VERSION ""

NS_ :

BS_:

BU_: MBMU PC SBMU IMM ETH DCDC LEMS

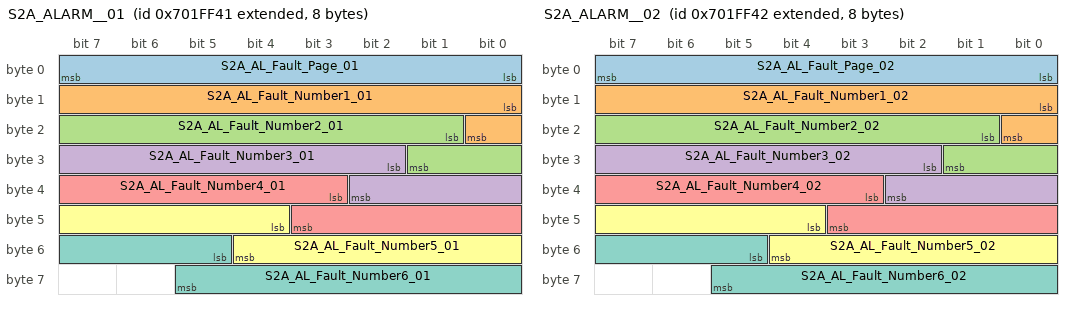
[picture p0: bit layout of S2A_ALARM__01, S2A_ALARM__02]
BO_ 2265055041 S2A_ALARM__01: 8 SBMU
 SG_ S2A_AL_Fault_Page_01 : 0|8@1+ (1,0) [0|255] ""  MBMU,PC
 SG_ S2A_AL_Fault_Number1_01 : 8|9@1+ (1,0) [0|511] ""  MBMU,PC
 SG_ S2A_AL_Fault_Number2_01 : 17|9@1+ (1,0) [0|511] ""  MBMU,PC
 SG_ S2A_AL_Fault_Number3_01 : 26|9@1+ (1,0) [0|511] ""  MBMU,PC
 SG_ S2A_AL_Fault_Number4_01 : 35|9@1+ (1,0) [0|511] ""  MBMU,PC
 SG_ S2A_AL_Fault_Number5_01 : 44|9@1+ (1,0) [0|511] ""  MBMU,PC
 SG_ S2A_AL_Fault_Number6_01 : 53|9@1+ (1,0) [0|511] ""  MBMU,PC

BO_ 2265055042 S2A_ALARM__02: 8 SBMU
 SG_ S2A_AL_Fault_Page_02 : 0|8@1+ (1,0) [0|255] ""  MBMU,PC
 SG_ S2A_AL_Fault_Number1_02 : 8|9@1+ (1,0) [0|511] ""  MBMU,PC
 SG_ S2A_AL_Fault_Number2_02 : 17|9@1+ (1,0) [0|511] ""  MBMU,PC
 SG_ S2A_AL_Fault_Number3_02 : 26|9@1+ (1,0) [0|511] ""  MBMU,PC
 SG_ S2A_AL_Fault_Number4_02 : 35|9@1+ (1,0) [0|511] ""  MBMU,PC
 SG_ S2A_AL_Fault_Number5_02 : 44|9@1+ (1,0) [0|511] ""  MBMU,PC
 SG_ S2A_AL_Fault_Number6_02 : 53|9@1+ (1,0) [0|511] ""  MBMU,PC

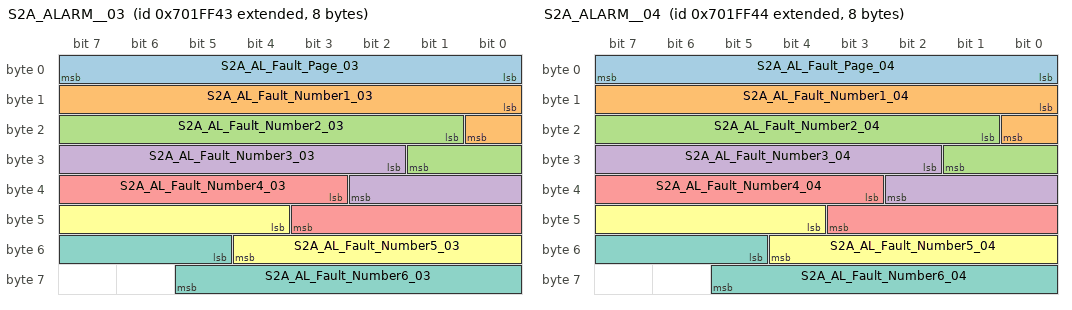
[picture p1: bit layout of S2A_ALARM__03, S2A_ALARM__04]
BO_ 2265055043 S2A_ALARM__03: 8 SBMU
 SG_ S2A_AL_Fault_Page_03 : 0|8@1+ (1,0) [0|255] ""  MBMU,PC
 SG_ S2A_AL_Fault_Number1_03 : 8|9@1+ (1,0) [0|511] ""  MBMU,PC
 SG_ S2A_AL_Fault_Number2_03 : 17|9@1+ (1,0) [0|511] ""  MBMU,PC
 SG_ S2A_AL_Fault_Number3_03 : 26|9@1+ (1,0) [0|511] ""  MBMU,PC
 SG_ S2A_AL_Fault_Number4_03 : 35|9@1+ (1,0) [0|511] ""  MBMU,PC
 SG_ S2A_AL_Fault_Number5_03 : 44|9@1+ (1,0) [0|511] ""  MBMU,PC
 SG_ S2A_AL_Fault_Number6_03 : 53|9@1+ (1,0) [0|511] ""  MBMU,PC

BO_ 2265055044 S2A_ALARM__04: 8 SBMU
 SG_ S2A_AL_Fault_Page_04 : 0|8@1+ (1,0) [0|255] ""  MBMU,PC
 SG_ S2A_AL_Fault_Number1_04 : 8|9@1+ (1,0) [0|511] ""  MBMU,PC
 SG_ S2A_AL_Fault_Number2_04 : 17|9@1+ (1,0) [0|511] ""  MBMU,PC
 SG_ S2A_AL_Fault_Number3_04 : 26|9@1+ (1,0) [0|511] ""  MBMU,PC
 SG_ S2A_AL_Fault_Number4_04 : 35|9@1+ (1,0) [0|511] ""  MBMU,PC
 SG_ S2A_AL_Fault_Number5_04 : 44|9@1+ (1,0) [0|511] ""  MBMU,PC
 SG_ S2A_AL_Fault_Number6_04 : 53|9@1+ (1,0) [0|511] ""  MBMU,PC

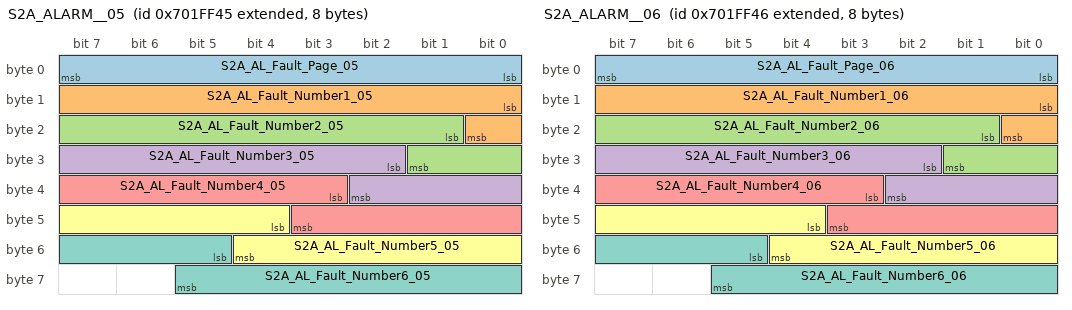
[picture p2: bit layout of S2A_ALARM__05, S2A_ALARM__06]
BO_ 2265055045 S2A_ALARM__05: 8 SBMU
 SG_ S2A_AL_Fault_Page_05 : 0|8@1+ (1,0) [0|255] ""  MBMU,PC
 SG_ S2A_AL_Fault_Number1_05 : 8|9@1+ (1,0) [0|511] ""  MBMU,PC
 SG_ S2A_AL_Fault_Number2_05 : 17|9@1+ (1,0) [0|511] ""  MBMU,PC
 SG_ S2A_AL_Fault_Number3_05 : 26|9@1+ (1,0) [0|511] ""  MBMU,PC
 SG_ S2A_AL_Fault_Number4_05 : 35|9@1+ (1,0) [0|511] ""  MBMU,PC
 SG_ S2A_AL_Fault_Number5_05 : 44|9@1+ (1,0) [0|511] ""  MBMU,PC
 SG_ S2A_AL_Fault_Number6_05 : 53|9@1+ (1,0) [0|511] ""  MBMU,PC

BO_ 2265055046 S2A_ALARM__06: 8 SBMU
 SG_ S2A_AL_Fault_Page_06 : 0|8@1+ (1,0) [0|255] ""  MBMU,PC
 SG_ S2A_AL_Fault_Number1_06 : 8|9@1+ (1,0) [0|511] ""  MBMU,PC
 SG_ S2A_AL_Fault_Number2_06 : 17|9@1+ (1,0) [0|511] ""  MBMU,PC
 SG_ S2A_AL_Fault_Number3_06 : 26|9@1+ (1,0) [0|511] ""  MBMU,PC
 SG_ S2A_AL_Fault_Number4_06 : 35|9@1+ (1,0) [0|511] ""  MBMU,PC
 SG_ S2A_AL_Fault_Number5_06 : 44|9@1+ (1,0) [0|511] ""  MBMU,PC
 SG_ S2A_AL_Fault_Number6_06 : 53|9@1+ (1,0) [0|511] ""  MBMU,PC

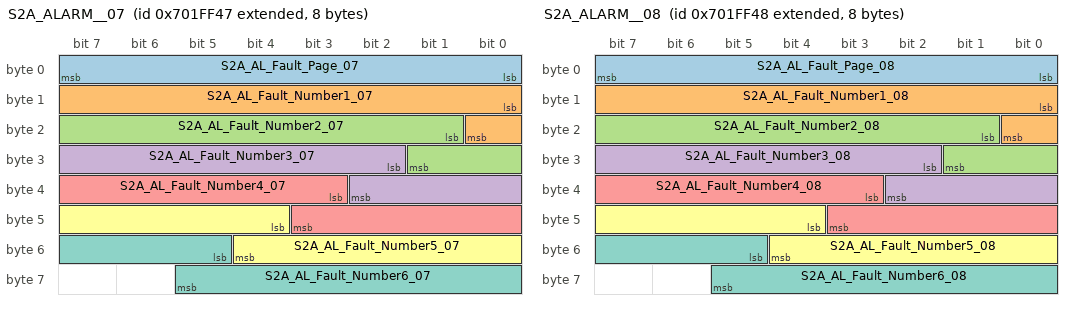
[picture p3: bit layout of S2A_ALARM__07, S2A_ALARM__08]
BO_ 2265055047 S2A_ALARM__07: 8 SBMU
 SG_ S2A_AL_Fault_Page_07 : 0|8@1+ (1,0) [0|255] ""  MBMU,PC
 SG_ S2A_AL_Fault_Number1_07 : 8|9@1+ (1,0) [0|511] ""  MBMU,PC
 SG_ S2A_AL_Fault_Number2_07 : 17|9@1+ (1,0) [0|511] ""  MBMU,PC
 SG_ S2A_AL_Fault_Number3_07 : 26|9@1+ (1,0) [0|511] ""  MBMU,PC
 SG_ S2A_AL_Fault_Number4_07 : 35|9@1+ (1,0) [0|511] ""  MBMU,PC
 SG_ S2A_AL_Fault_Number5_07 : 44|9@1+ (1,0) [0|511] ""  MBMU,PC
 SG_ S2A_AL_Fault_Number6_07 : 53|9@1+ (1,0) [0|511] ""  MBMU,PC

BO_ 2265055048 S2A_ALARM__08: 8 SBMU
 SG_ S2A_AL_Fault_Page_08 : 0|8@1+ (1,0) [0|255] ""  MBMU,PC
 SG_ S2A_AL_Fault_Number1_08 : 8|9@1+ (1,0) [0|511] ""  MBMU,PC
 SG_ S2A_AL_Fault_Number2_08 : 17|9@1+ (1,0) [0|511] ""  MBMU,PC
 SG_ S2A_AL_Fault_Number3_08 : 26|9@1+ (1,0) [0|511] ""  MBMU,PC
 SG_ S2A_AL_Fault_Number4_08 : 35|9@1+ (1,0) [0|511] ""  MBMU,PC
 SG_ S2A_AL_Fault_Number5_08 : 44|9@1+ (1,0) [0|511] ""  MBMU,PC
 SG_ S2A_AL_Fault_Number6_08 : 53|9@1+ (1,0) [0|511] ""  MBMU,PC

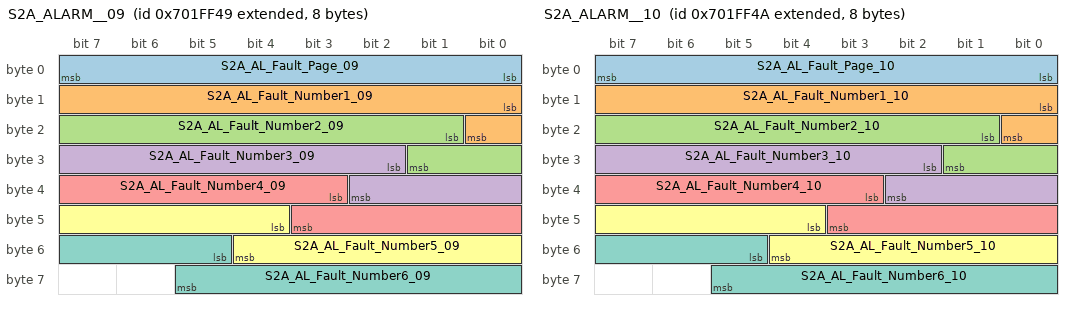
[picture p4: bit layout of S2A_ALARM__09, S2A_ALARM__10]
BO_ 2265055049 S2A_ALARM__09: 8 SBMU
 SG_ S2A_AL_Fault_Page_09 : 0|8@1+ (1,0) [0|255] ""  MBMU,PC
 SG_ S2A_AL_Fault_Number1_09 : 8|9@1+ (1,0) [0|511] ""  MBMU,PC
 SG_ S2A_AL_Fault_Number2_09 : 17|9@1+ (1,0) [0|511] ""  MBMU,PC
 SG_ S2A_AL_Fault_Number3_09 : 26|9@1+ (1,0) [0|511] ""  MBMU,PC
 SG_ S2A_AL_Fault_Number4_09 : 35|9@1+ (1,0) [0|511] ""  MBMU,PC
 SG_ S2A_AL_Fault_Number5_09 : 44|9@1+ (1,0) [0|511] ""  MBMU,PC
 SG_ S2A_AL_Fault_Number6_09 : 53|9@1+ (1,0) [0|511] ""  MBMU,PC

BO_ 2265055050 S2A_ALARM__10: 8 SBMU
 SG_ S2A_AL_Fault_Page_10 : 0|8@1+ (1,0) [0|255] ""  MBMU,PC
 SG_ S2A_AL_Fault_Number1_10 : 8|9@1+ (1,0) [0|511] ""  MBMU,PC
 SG_ S2A_AL_Fault_Number2_10 : 17|9@1+ (1,0) [0|511] ""  MBMU,PC
 SG_ S2A_AL_Fault_Number3_10 : 26|9@1+ (1,0) [0|511] ""  MBMU,PC
 SG_ S2A_AL_Fault_Number4_10 : 35|9@1+ (1,0) [0|511] ""  MBMU,PC
 SG_ S2A_AL_Fault_Number5_10 : 44|9@1+ (1,0) [0|511] ""  MBMU,PC
 SG_ S2A_AL_Fault_Number6_10 : 53|9@1+ (1,0) [0|511] ""  MBMU,PC

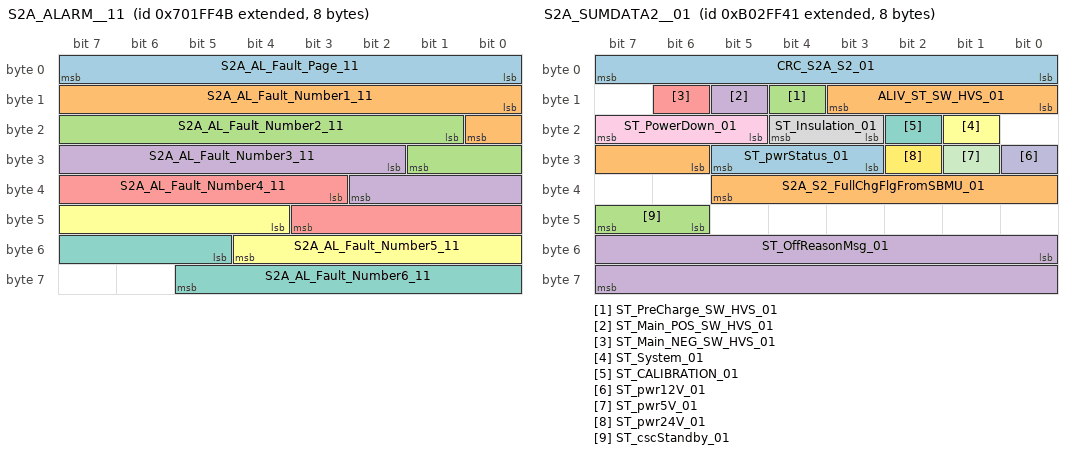
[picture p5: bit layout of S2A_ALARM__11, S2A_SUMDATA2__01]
BO_ 2265055051 S2A_ALARM__11: 8 SBMU
 SG_ S2A_AL_Fault_Page_11 : 0|8@1+ (1,0) [0|255] ""  MBMU,PC
 SG_ S2A_AL_Fault_Number1_11 : 8|9@1+ (1,0) [0|511] ""  MBMU,PC
 SG_ S2A_AL_Fault_Number2_11 : 17|9@1+ (1,0) [0|511] ""  MBMU,PC
 SG_ S2A_AL_Fault_Number3_11 : 26|9@1+ (1,0) [0|511] ""  MBMU,PC
 SG_ S2A_AL_Fault_Number4_11 : 35|9@1+ (1,0) [0|511] ""  MBMU,PC
 SG_ S2A_AL_Fault_Number5_11 : 44|9@1+ (1,0) [0|511] ""  MBMU,PC
 SG_ S2A_AL_Fault_Number6_11 : 53|9@1+ (1,0) [0|511] ""  MBMU,PC

BO_ 2265055052 S2A_ALARM__12: 8 SBMU
 SG_ S2A_AL_Fault_Page_12 : 0|8@1+ (1,0) [0|255] ""  MBMU,PC
 SG_ S2A_AL_Fault_Number1_12 : 8|9@1+ (1,0) [0|511] ""  MBMU,PC
 SG_ S2A_AL_Fault_Number2_12 : 17|9@1+ (1,0) [0|511] ""  MBMU,PC
 SG_ S2A_AL_Fault_Number3_12 : 26|9@1+ (1,0) [0|511] ""  MBMU,PC
 SG_ S2A_AL_Fault_Number4_12 : 35|9@1+ (1,0) [0|511] ""  MBMU,PC
 SG_ S2A_AL_Fault_Number5_12 : 44|9@1+ (1,0) [0|511] ""  MBMU,PC
 SG_ S2A_AL_Fault_Number6_12 : 53|9@1+ (1,0) [0|511] ""  MBMU,PC

BO_ 2265055053 S2A_ALARM__13: 8 SBMU
 SG_ S2A_AL_Fault_Page_13 : 0|8@1+ (1,0) [0|255] ""  MBMU,PC
 SG_ S2A_AL_Fault_Number1_13 : 8|9@1+ (1,0) [0|511] ""  MBMU,PC
 SG_ S2A_AL_Fault_Number2_13 : 17|9@1+ (1,0) [0|511] ""  MBMU,PC
 SG_ S2A_AL_Fault_Number3_13 : 26|9@1+ (1,0) [0|511] ""  MBMU,PC
 SG_ S2A_AL_Fault_Number4_13 : 35|9@1+ (1,0) [0|511] ""  MBMU,PC
 SG_ S2A_AL_Fault_Number5_13 : 44|9@1+ (1,0) [0|511] ""  MBMU,PC
 SG_ S2A_AL_Fault_Number6_13 : 53|9@1+ (1,0) [0|511] ""  MBMU,PC

BO_ 2265055054 S2A_ALARM__14: 8 SBMU
 SG_ S2A_AL_Fault_Page_14 : 0|8@1+ (1,0) [0|255] ""  MBMU,PC
 SG_ S2A_AL_Fault_Number1_14 : 8|9@1+ (1,0) [0|511] ""  MBMU,PC
 SG_ S2A_AL_Fault_Number2_14 : 17|9@1+ (1,0) [0|511] ""  MBMU,PC
 SG_ S2A_AL_Fault_Number3_14 : 26|9@1+ (1,0) [0|511] ""  MBMU,PC
 SG_ S2A_AL_Fault_Number4_14 : 35|9@1+ (1,0) [0|511] ""  MBMU,PC
 SG_ S2A_AL_Fault_Number5_14 : 44|9@1+ (1,0) [0|511] ""  MBMU,PC
 SG_ S2A_AL_Fault_Number6_14 : 53|9@1+ (1,0) [0|511] ""  MBMU,PC

BO_ 2265055055 S2A_ALARM__15: 8 SBMU
 SG_ S2A_AL_Fault_Page_15 : 0|8@1+ (1,0) [0|255] ""  MBMU,PC
 SG_ S2A_AL_Fault_Number1_15 : 8|9@1+ (1,0) [0|511] ""  MBMU,PC
 SG_ S2A_AL_Fault_Number2_15 : 17|9@1+ (1,0) [0|511] ""  MBMU,PC
 SG_ S2A_AL_Fault_Number3_15 : 26|9@1+ (1,0) [0|511] ""  MBMU,PC
 SG_ S2A_AL_Fault_Number4_15 : 35|9@1+ (1,0) [0|511] ""  MBMU,PC
 SG_ S2A_AL_Fault_Number5_15 : 44|9@1+ (1,0) [0|511] ""  MBMU,PC
 SG_ S2A_AL_Fault_Number6_15 : 53|9@1+ (1,0) [0|511] ""  MBMU,PC

BO_ 2265055056 S2A_ALARM__16: 8 SBMU
 SG_ S2A_AL_Fault_Page_16 : 0|8@1+ (1,0) [0|255] ""  MBMU,PC
 SG_ S2A_AL_Fault_Number1_16 : 8|9@1+ (1,0) [0|511] ""  MBMU,PC
 SG_ S2A_AL_Fault_Number2_16 : 17|9@1+ (1,0) [0|511] ""  MBMU,PC
 SG_ S2A_AL_Fault_Number3_16 : 26|9@1+ (1,0) [0|511] ""  MBMU,PC
 SG_ S2A_AL_Fault_Number4_16 : 35|9@1+ (1,0) [0|511] ""  MBMU,PC
 SG_ S2A_AL_Fault_Number5_16 : 44|9@1+ (1,0) [0|511] ""  MBMU,PC
 SG_ S2A_AL_Fault_Number6_16 : 53|9@1+ (1,0) [0|511] ""  MBMU,PC

BO_ 2265055057 S2A_ALARM__17: 8 SBMU
 SG_ S2A_AL_Fault_Page_17 : 0|8@1+ (1,0) [0|255] ""  MBMU,PC
 SG_ S2A_AL_Fault_Number1_17 : 8|9@1+ (1,0) [0|511] ""  MBMU,PC
 SG_ S2A_AL_Fault_Number2_17 : 17|9@1+ (1,0) [0|511] ""  MBMU,PC
 SG_ S2A_AL_Fault_Number3_17 : 26|9@1+ (1,0) [0|511] ""  MBMU,PC
 SG_ S2A_AL_Fault_Number4_17 : 35|9@1+ (1,0) [0|511] ""  MBMU,PC
 SG_ S2A_AL_Fault_Number5_17 : 44|9@1+ (1,0) [0|511] ""  MBMU,PC
 SG_ S2A_AL_Fault_Number6_17 : 53|9@1+ (1,0) [0|511] ""  MBMU,PC

BO_ 2265055058 S2A_ALARM__18: 8 SBMU
 SG_ S2A_AL_Fault_Page_18 : 0|8@1+ (1,0) [0|255] ""  MBMU,PC
 SG_ S2A_AL_Fault_Number1_18 : 8|9@1+ (1,0) [0|511] ""  MBMU,PC
 SG_ S2A_AL_Fault_Number2_18 : 17|9@1+ (1,0) [0|511] ""  MBMU,PC
 SG_ S2A_AL_Fault_Number3_18 : 26|9@1+ (1,0) [0|511] ""  MBMU,PC
 SG_ S2A_AL_Fault_Number4_18 : 35|9@1+ (1,0) [0|511] ""  MBMU,PC
 SG_ S2A_AL_Fault_Number5_18 : 44|9@1+ (1,0) [0|511] ""  MBMU,PC
 SG_ S2A_AL_Fault_Number6_18 : 53|9@1+ (1,0) [0|511] ""  MBMU,PC

BO_ 2265055059 S2A_ALARM__19: 8 SBMU
 SG_ S2A_AL_Fault_Page_19 : 0|8@1+ (1,0) [0|255] ""  MBMU,PC
 SG_ S2A_AL_Fault_Number1_19 : 8|9@1+ (1,0) [0|511] ""  MBMU,PC
 SG_ S2A_AL_Fault_Number2_19 : 17|9@1+ (1,0) [0|511] ""  MBMU,PC
 SG_ S2A_AL_Fault_Number3_19 : 26|9@1+ (1,0) [0|511] ""  MBMU,PC
 SG_ S2A_AL_Fault_Number4_19 : 35|9@1+ (1,0) [0|511] ""  MBMU,PC
 SG_ S2A_AL_Fault_Number5_19 : 44|9@1+ (1,0) [0|511] ""  MBMU,PC
 SG_ S2A_AL_Fault_Number6_19 : 53|9@1+ (1,0) [0|511] ""  MBMU,PC

BO_ 2265055060 S2A_ALARM__20: 8 SBMU
 SG_ S2A_AL_Fault_Page_20 : 0|8@1+ (1,0) [0|255] ""  MBMU,PC
 SG_ S2A_AL_Fault_Number1_20 : 8|9@1+ (1,0) [0|511] ""  MBMU,PC
 SG_ S2A_AL_Fault_Number2_20 : 17|9@1+ (1,0) [0|511] ""  MBMU,PC
 SG_ S2A_AL_Fault_Number3_20 : 26|9@1+ (1,0) [0|511] ""  MBMU,PC
 SG_ S2A_AL_Fault_Number4_20 : 35|9@1+ (1,0) [0|511] ""  MBMU,PC
 SG_ S2A_AL_Fault_Number5_20 : 44|9@1+ (1,0) [0|511] ""  MBMU,PC
 SG_ S2A_AL_Fault_Number6_20 : 53|9@1+ (1,0) [0|511] ""  MBMU,PC

BO_ 2265055061 S2A_ALARM__21: 8 SBMU
 SG_ S2A_AL_Fault_Page_21 : 0|8@1+ (1,0) [0|255] ""  MBMU,PC
 SG_ S2A_AL_Fault_Number1_21 : 8|9@1+ (1,0) [0|511] ""  MBMU,PC
 SG_ S2A_AL_Fault_Number2_21 : 17|9@1+ (1,0) [0|511] ""  MBMU,PC
 SG_ S2A_AL_Fault_Number3_21 : 26|9@1+ (1,0) [0|511] ""  MBMU,PC
 SG_ S2A_AL_Fault_Number4_21 : 35|9@1+ (1,0) [0|511] ""  MBMU,PC
 SG_ S2A_AL_Fault_Number5_21 : 44|9@1+ (1,0) [0|511] ""  MBMU,PC
 SG_ S2A_AL_Fault_Number6_21 : 53|9@1+ (1,0) [0|511] ""  MBMU,PC

BO_ 2265055062 S2A_ALARM__22: 8 SBMU
 SG_ S2A_AL_Fault_Page_22 : 0|8@1+ (1,0) [0|255] ""  MBMU,PC
 SG_ S2A_AL_Fault_Number1_22 : 8|9@1+ (1,0) [0|511] ""  MBMU,PC
 SG_ S2A_AL_Fault_Number2_22 : 17|9@1+ (1,0) [0|511] ""  MBMU,PC
 SG_ S2A_AL_Fault_Number3_22 : 26|9@1+ (1,0) [0|511] ""  MBMU,PC
 SG_ S2A_AL_Fault_Number4_22 : 35|9@1+ (1,0) [0|511] ""  MBMU,PC
 SG_ S2A_AL_Fault_Number5_22 : 44|9@1+ (1,0) [0|511] ""  MBMU,PC
 SG_ S2A_AL_Fault_Number6_22 : 53|9@1+ (1,0) [0|511] ""  MBMU,PC

BO_ 2265055063 S2A_ALARM__23: 8 SBMU
 SG_ S2A_AL_Fault_Page_23 : 0|8@1+ (1,0) [0|255] ""  MBMU,PC
 SG_ S2A_AL_Fault_Number1_23 : 8|9@1+ (1,0) [0|511] ""  MBMU,PC
 SG_ S2A_AL_Fault_Number2_23 : 17|9@1+ (1,0) [0|511] ""  MBMU,PC
 SG_ S2A_AL_Fault_Number3_23 : 26|9@1+ (1,0) [0|511] ""  MBMU,PC
 SG_ S2A_AL_Fault_Number4_23 : 35|9@1+ (1,0) [0|511] ""  MBMU,PC
 SG_ S2A_AL_Fault_Number5_23 : 44|9@1+ (1,0) [0|511] ""  MBMU,PC
 SG_ S2A_AL_Fault_Number6_23 : 53|9@1+ (1,0) [0|511] ""  MBMU,PC

BO_ 2265055064 S2A_ALARM__24: 8 SBMU
 SG_ S2A_AL_Fault_Page_24 : 0|8@1+ (1,0) [0|255] ""  MBMU,PC
 SG_ S2A_AL_Fault_Number1_24 : 8|9@1+ (1,0) [0|511] ""  MBMU,PC
 SG_ S2A_AL_Fault_Number2_24 : 17|9@1+ (1,0) [0|511] ""  MBMU,PC
 SG_ S2A_AL_Fault_Number3_24 : 26|9@1+ (1,0) [0|511] ""  MBMU,PC
 SG_ S2A_AL_Fault_Number4_24 : 35|9@1+ (1,0) [0|511] ""  MBMU,PC
 SG_ S2A_AL_Fault_Number5_24 : 44|9@1+ (1,0) [0|511] ""  MBMU,PC
 SG_ S2A_AL_Fault_Number6_24 : 53|9@1+ (1,0) [0|511] ""  MBMU,PC

BO_ 2265055065 S2A_ALARM__25: 8 SBMU
 SG_ S2A_AL_Fault_Page_25 : 0|8@1+ (1,0) [0|255] ""  MBMU,PC
 SG_ S2A_AL_Fault_Number1_25 : 8|9@1+ (1,0) [0|511] ""  MBMU,PC
 SG_ S2A_AL_Fault_Number2_25 : 17|9@1+ (1,0) [0|511] ""  MBMU,PC
 SG_ S2A_AL_Fault_Number3_25 : 26|9@1+ (1,0) [0|511] ""  MBMU,PC
 SG_ S2A_AL_Fault_Number4_25 : 35|9@1+ (1,0) [0|511] ""  MBMU,PC
 SG_ S2A_AL_Fault_Number5_25 : 44|9@1+ (1,0) [0|511] ""  MBMU,PC
 SG_ S2A_AL_Fault_Number6_25 : 53|9@1+ (1,0) [0|511] ""  MBMU,PC

BO_ 2265055066 S2A_ALARM__26: 8 SBMU
 SG_ S2A_AL_Fault_Page_26 : 0|8@1+ (1,0) [0|255] ""  MBMU,PC
 SG_ S2A_AL_Fault_Number1_26 : 8|9@1+ (1,0) [0|511] ""  MBMU,PC
 SG_ S2A_AL_Fault_Number2_26 : 17|9@1+ (1,0) [0|511] ""  MBMU,PC
 SG_ S2A_AL_Fault_Number3_26 : 26|9@1+ (1,0) [0|511] ""  MBMU,PC
 SG_ S2A_AL_Fault_Number4_26 : 35|9@1+ (1,0) [0|511] ""  MBMU,PC
 SG_ S2A_AL_Fault_Number5_26 : 44|9@1+ (1,0) [0|511] ""  MBMU,PC
 SG_ S2A_AL_Fault_Number6_26 : 53|9@1+ (1,0) [0|511] ""  MBMU,PC

BO_ 2265055067 S2A_ALARM__27: 8 SBMU
 SG_ S2A_AL_Fault_Page_27 : 0|8@1+ (1,0) [0|255] ""  MBMU,PC
 SG_ S2A_AL_Fault_Number1_27 : 8|9@1+ (1,0) [0|511] ""  MBMU,PC
 SG_ S2A_AL_Fault_Number2_27 : 17|9@1+ (1,0) [0|511] ""  MBMU,PC
 SG_ S2A_AL_Fault_Number3_27 : 26|9@1+ (1,0) [0|511] ""  MBMU,PC
 SG_ S2A_AL_Fault_Number4_27 : 35|9@1+ (1,0) [0|511] ""  MBMU,PC
 SG_ S2A_AL_Fault_Number5_27 : 44|9@1+ (1,0) [0|511] ""  MBMU,PC
 SG_ S2A_AL_Fault_Number6_27 : 53|9@1+ (1,0) [0|511] ""  MBMU,PC

BO_ 2265055068 S2A_ALARM__28: 8 SBMU
 SG_ S2A_AL_Fault_Page_28 : 0|8@1+ (1,0) [0|255] ""  MBMU,PC
 SG_ S2A_AL_Fault_Number1_28 : 8|9@1+ (1,0) [0|511] ""  MBMU,PC
 SG_ S2A_AL_Fault_Number2_28 : 17|9@1+ (1,0) [0|511] ""  MBMU,PC
 SG_ S2A_AL_Fault_Number3_28 : 26|9@1+ (1,0) [0|511] ""  MBMU,PC
 SG_ S2A_AL_Fault_Number4_28 : 35|9@1+ (1,0) [0|511] ""  MBMU,PC
 SG_ S2A_AL_Fault_Number5_28 : 44|9@1+ (1,0) [0|511] ""  MBMU,PC
 SG_ S2A_AL_Fault_Number6_28 : 53|9@1+ (1,0) [0|511] ""  MBMU,PC

BO_ 2265055069 S2A_ALARM__29: 8 SBMU
 SG_ S2A_AL_Fault_Page_29 : 0|8@1+ (1,0) [0|255] ""  MBMU,PC
 SG_ S2A_AL_Fault_Number1_29 : 8|9@1+ (1,0) [0|511] ""  MBMU,PC
 SG_ S2A_AL_Fault_Number2_29 : 17|9@1+ (1,0) [0|511] ""  MBMU,PC
 SG_ S2A_AL_Fault_Number3_29 : 26|9@1+ (1,0) [0|511] ""  MBMU,PC
 SG_ S2A_AL_Fault_Number4_29 : 35|9@1+ (1,0) [0|511] ""  MBMU,PC
 SG_ S2A_AL_Fault_Number5_29 : 44|9@1+ (1,0) [0|511] ""  MBMU,PC
 SG_ S2A_AL_Fault_Number6_29 : 53|9@1+ (1,0) [0|511] ""  MBMU,PC

BO_ 2265055070 S2A_ALARM__30: 8 SBMU
 SG_ S2A_AL_Fault_Page_30 : 0|8@1+ (1,0) [0|255] ""  MBMU,PC
 SG_ S2A_AL_Fault_Number1_30 : 8|9@1+ (1,0) [0|511] ""  MBMU,PC
 SG_ S2A_AL_Fault_Number2_30 : 17|9@1+ (1,0) [0|511] ""  MBMU,PC
 SG_ S2A_AL_Fault_Number3_30 : 26|9@1+ (1,0) [0|511] ""  MBMU,PC
 SG_ S2A_AL_Fault_Number4_30 : 35|9@1+ (1,0) [0|511] ""  MBMU,PC
 SG_ S2A_AL_Fault_Number5_30 : 44|9@1+ (1,0) [0|511] ""  MBMU,PC
 SG_ S2A_AL_Fault_Number6_30 : 53|9@1+ (1,0) [0|511] ""  MBMU,PC

BO_ 2265055071 S2A_ALARM__31: 8 SBMU
 SG_ S2A_AL_Fault_Page_31 : 0|8@1+ (1,0) [0|255] ""  MBMU,PC
 SG_ S2A_AL_Fault_Number1_31 : 8|9@1+ (1,0) [0|511] ""  MBMU,PC
 SG_ S2A_AL_Fault_Number2_31 : 17|9@1+ (1,0) [0|511] ""  MBMU,PC
 SG_ S2A_AL_Fault_Number3_31 : 26|9@1+ (1,0) [0|511] ""  MBMU,PC
 SG_ S2A_AL_Fault_Number4_31 : 35|9@1+ (1,0) [0|511] ""  MBMU,PC
 SG_ S2A_AL_Fault_Number5_31 : 44|9@1+ (1,0) [0|511] ""  MBMU,PC
 SG_ S2A_AL_Fault_Number6_31 : 53|9@1+ (1,0) [0|511] ""  MBMU,PC

BO_ 2265055072 S2A_ALARM__32: 8 SBMU
 SG_ S2A_AL_Fault_Page_32 : 0|8@1+ (1,0) [0|255] ""  MBMU,PC
 SG_ S2A_AL_Fault_Number1_32 : 8|9@1+ (1,0) [0|511] ""  MBMU,PC
 SG_ S2A_AL_Fault_Number2_32 : 17|9@1+ (1,0) [0|511] ""  MBMU,PC
 SG_ S2A_AL_Fault_Number3_32 : 26|9@1+ (1,0) [0|511] ""  MBMU,PC
 SG_ S2A_AL_Fault_Number4_32 : 35|9@1+ (1,0) [0|511] ""  MBMU,PC
 SG_ S2A_AL_Fault_Number5_32 : 44|9@1+ (1,0) [0|511] ""  MBMU,PC
 SG_ S2A_AL_Fault_Number6_32 : 53|9@1+ (1,0) [0|511] ""  MBMU,PC

BO_ 2265055073 S2A_ALARM__33: 8 SBMU
 SG_ S2A_AL_Fault_Page_33 : 0|8@1+ (1,0) [0|255] ""  MBMU,PC
 SG_ S2A_AL_Fault_Number1_33 : 8|9@1+ (1,0) [0|511] ""  MBMU,PC
 SG_ S2A_AL_Fault_Number2_33 : 17|9@1+ (1,0) [0|511] ""  MBMU,PC
 SG_ S2A_AL_Fault_Number3_33 : 26|9@1+ (1,0) [0|511] ""  MBMU,PC
 SG_ S2A_AL_Fault_Number4_33 : 35|9@1+ (1,0) [0|511] ""  MBMU,PC
 SG_ S2A_AL_Fault_Number5_33 : 44|9@1+ (1,0) [0|511] ""  MBMU,PC
 SG_ S2A_AL_Fault_Number6_33 : 53|9@1+ (1,0) [0|511] ""  MBMU,PC

BO_ 2265055074 S2A_ALARM__34: 8 SBMU
 SG_ S2A_AL_Fault_Page_34 : 0|8@1+ (1,0) [0|255] ""  MBMU,PC
 SG_ S2A_AL_Fault_Number1_34 : 8|9@1+ (1,0) [0|511] ""  MBMU,PC
 SG_ S2A_AL_Fault_Number2_34 : 17|9@1+ (1,0) [0|511] ""  MBMU,PC
 SG_ S2A_AL_Fault_Number3_34 : 26|9@1+ (1,0) [0|511] ""  MBMU,PC
 SG_ S2A_AL_Fault_Number4_34 : 35|9@1+ (1,0) [0|511] ""  MBMU,PC
 SG_ S2A_AL_Fault_Number5_34 : 44|9@1+ (1,0) [0|511] ""  MBMU,PC
 SG_ S2A_AL_Fault_Number6_34 : 53|9@1+ (1,0) [0|511] ""  MBMU,PC

BO_ 2265055075 S2A_ALARM__35: 8 SBMU
 SG_ S2A_AL_Fault_Page_35 : 0|8@1+ (1,0) [0|255] ""  MBMU,PC
 SG_ S2A_AL_Fault_Number1_35 : 8|9@1+ (1,0) [0|511] ""  MBMU,PC
 SG_ S2A_AL_Fault_Number2_35 : 17|9@1+ (1,0) [0|511] ""  MBMU,PC
 SG_ S2A_AL_Fault_Number3_35 : 26|9@1+ (1,0) [0|511] ""  MBMU,PC
 SG_ S2A_AL_Fault_Number4_35 : 35|9@1+ (1,0) [0|511] ""  MBMU,PC
 SG_ S2A_AL_Fault_Number5_35 : 44|9@1+ (1,0) [0|511] ""  MBMU,PC
 SG_ S2A_AL_Fault_Number6_35 : 53|9@1+ (1,0) [0|511] ""  MBMU,PC

BO_ 2265055076 S2A_ALARM__36: 8 SBMU
 SG_ S2A_AL_Fault_Page_36 : 0|8@1+ (1,0) [0|255] ""  MBMU,PC
 SG_ S2A_AL_Fault_Number1_36 : 8|9@1+ (1,0) [0|511] ""  MBMU,PC
 SG_ S2A_AL_Fault_Number2_36 : 17|9@1+ (1,0) [0|511] ""  MBMU,PC
 SG_ S2A_AL_Fault_Number3_36 : 26|9@1+ (1,0) [0|511] ""  MBMU,PC
 SG_ S2A_AL_Fault_Number4_36 : 35|9@1+ (1,0) [0|511] ""  MBMU,PC
 SG_ S2A_AL_Fault_Number5_36 : 44|9@1+ (1,0) [0|511] ""  MBMU,PC
 SG_ S2A_AL_Fault_Number6_36 : 53|9@1+ (1,0) [0|511] ""  MBMU,PC

BO_ 2265055077 S2A_ALARM__37: 8 SBMU
 SG_ S2A_AL_Fault_Page_37 : 0|8@1+ (1,0) [0|255] ""  MBMU,PC
 SG_ S2A_AL_Fault_Number1_37 : 8|9@1+ (1,0) [0|511] ""  MBMU,PC
 SG_ S2A_AL_Fault_Number2_37 : 17|9@1+ (1,0) [0|511] ""  MBMU,PC
 SG_ S2A_AL_Fault_Number3_37 : 26|9@1+ (1,0) [0|511] ""  MBMU,PC
 SG_ S2A_AL_Fault_Number4_37 : 35|9@1+ (1,0) [0|511] ""  MBMU,PC
 SG_ S2A_AL_Fault_Number5_37 : 44|9@1+ (1,0) [0|511] ""  MBMU,PC
 SG_ S2A_AL_Fault_Number6_37 : 53|9@1+ (1,0) [0|511] ""  MBMU,PC

BO_ 2265055078 S2A_ALARM__38: 8 SBMU
 SG_ S2A_AL_Fault_Page_38 : 0|8@1+ (1,0) [0|255] ""  MBMU,PC
 SG_ S2A_AL_Fault_Number1_38 : 8|9@1+ (1,0) [0|511] ""  MBMU,PC
 SG_ S2A_AL_Fault_Number2_38 : 17|9@1+ (1,0) [0|511] ""  MBMU,PC
 SG_ S2A_AL_Fault_Number3_38 : 26|9@1+ (1,0) [0|511] ""  MBMU,PC
 SG_ S2A_AL_Fault_Number4_38 : 35|9@1+ (1,0) [0|511] ""  MBMU,PC
 SG_ S2A_AL_Fault_Number5_38 : 44|9@1+ (1,0) [0|511] ""  MBMU,PC
 SG_ S2A_AL_Fault_Number6_38 : 53|9@1+ (1,0) [0|511] ""  MBMU,PC

BO_ 2265055079 S2A_ALARM__39: 8 SBMU
 SG_ S2A_AL_Fault_Page_39 : 0|8@1+ (1,0) [0|255] ""  MBMU,PC
 SG_ S2A_AL_Fault_Number1_39 : 8|9@1+ (1,0) [0|511] ""  MBMU,PC
 SG_ S2A_AL_Fault_Number2_39 : 17|9@1+ (1,0) [0|511] ""  MBMU,PC
 SG_ S2A_AL_Fault_Number3_39 : 26|9@1+ (1,0) [0|511] ""  MBMU,PC
 SG_ S2A_AL_Fault_Number4_39 : 35|9@1+ (1,0) [0|511] ""  MBMU,PC
 SG_ S2A_AL_Fault_Number5_39 : 44|9@1+ (1,0) [0|511] ""  MBMU,PC
 SG_ S2A_AL_Fault_Number6_39 : 53|9@1+ (1,0) [0|511] ""  MBMU,PC

BO_ 2265055080 S2A_ALARM__40: 8 SBMU
 SG_ S2A_AL_Fault_Page_40 : 0|8@1+ (1,0) [0|255] ""  MBMU,PC
 SG_ S2A_AL_Fault_Number1_40 : 8|9@1+ (1,0) [0|511] ""  MBMU,PC
 SG_ S2A_AL_Fault_Number2_40 : 17|9@1+ (1,0) [0|511] ""  MBMU,PC
 SG_ S2A_AL_Fault_Number3_40 : 26|9@1+ (1,0) [0|511] ""  MBMU,PC
 SG_ S2A_AL_Fault_Number4_40 : 35|9@1+ (1,0) [0|511] ""  MBMU,PC
 SG_ S2A_AL_Fault_Number5_40 : 44|9@1+ (1,0) [0|511] ""  MBMU,PC
 SG_ S2A_AL_Fault_Number6_40 : 53|9@1+ (1,0) [0|511] ""  MBMU,PC

BO_ 2265055081 S2A_ALARM__41: 8 SBMU
 SG_ S2A_AL_Fault_Page_41 : 0|8@1+ (1,0) [0|255] ""  MBMU,PC
 SG_ S2A_AL_Fault_Number1_41 : 8|9@1+ (1,0) [0|511] ""  MBMU,PC
 SG_ S2A_AL_Fault_Number2_41 : 17|9@1+ (1,0) [0|511] ""  MBMU,PC
 SG_ S2A_AL_Fault_Number3_41 : 26|9@1+ (1,0) [0|511] ""  MBMU,PC
 SG_ S2A_AL_Fault_Number4_41 : 35|9@1+ (1,0) [0|511] ""  MBMU,PC
 SG_ S2A_AL_Fault_Number5_41 : 44|9@1+ (1,0) [0|511] ""  MBMU,PC
 SG_ S2A_AL_Fault_Number6_41 : 53|9@1+ (1,0) [0|511] ""  MBMU,PC

BO_ 2265055082 S2A_ALARM__42: 8 SBMU
 SG_ S2A_AL_Fault_Page_42 : 0|8@1+ (1,0) [0|255] ""  MBMU,PC
 SG_ S2A_AL_Fault_Number1_42 : 8|9@1+ (1,0) [0|511] ""  MBMU,PC
 SG_ S2A_AL_Fault_Number2_42 : 17|9@1+ (1,0) [0|511] ""  MBMU,PC
 SG_ S2A_AL_Fault_Number3_42 : 26|9@1+ (1,0) [0|511] ""  MBMU,PC
 SG_ S2A_AL_Fault_Number4_42 : 35|9@1+ (1,0) [0|511] ""  MBMU,PC
 SG_ S2A_AL_Fault_Number5_42 : 44|9@1+ (1,0) [0|511] ""  MBMU,PC
 SG_ S2A_AL_Fault_Number6_42 : 53|9@1+ (1,0) [0|511] ""  MBMU,PC

BO_ 2265055083 S2A_ALARM__43: 8 SBMU
 SG_ S2A_AL_Fault_Page_43 : 0|8@1+ (1,0) [0|255] ""  MBMU,PC
 SG_ S2A_AL_Fault_Number1_43 : 8|9@1+ (1,0) [0|511] ""  MBMU,PC
 SG_ S2A_AL_Fault_Number2_43 : 17|9@1+ (1,0) [0|511] ""  MBMU,PC
 SG_ S2A_AL_Fault_Number3_43 : 26|9@1+ (1,0) [0|511] ""  MBMU,PC
 SG_ S2A_AL_Fault_Number4_43 : 35|9@1+ (1,0) [0|511] ""  MBMU,PC
 SG_ S2A_AL_Fault_Number5_43 : 44|9@1+ (1,0) [0|511] ""  MBMU,PC
 SG_ S2A_AL_Fault_Number6_43 : 53|9@1+ (1,0) [0|511] ""  MBMU,PC

BO_ 2265055084 S2A_ALARM__44: 8 SBMU
 SG_ S2A_AL_Fault_Page_44 : 0|8@1+ (1,0) [0|255] ""  MBMU,PC
 SG_ S2A_AL_Fault_Number1_44 : 8|9@1+ (1,0) [0|511] ""  MBMU,PC
 SG_ S2A_AL_Fault_Number2_44 : 17|9@1+ (1,0) [0|511] ""  MBMU,PC
 SG_ S2A_AL_Fault_Number3_44 : 26|9@1+ (1,0) [0|511] ""  MBMU,PC
 SG_ S2A_AL_Fault_Number4_44 : 35|9@1+ (1,0) [0|511] ""  MBMU,PC
 SG_ S2A_AL_Fault_Number5_44 : 44|9@1+ (1,0) [0|511] ""  MBMU,PC
 SG_ S2A_AL_Fault_Number6_44 : 53|9@1+ (1,0) [0|511] ""  MBMU,PC

BO_ 2265055085 S2A_ALARM__45: 8 SBMU
 SG_ S2A_AL_Fault_Page_45 : 0|8@1+ (1,0) [0|255] ""  MBMU,PC
 SG_ S2A_AL_Fault_Number1_45 : 8|9@1+ (1,0) [0|511] ""  MBMU,PC
 SG_ S2A_AL_Fault_Number2_45 : 17|9@1+ (1,0) [0|511] ""  MBMU,PC
 SG_ S2A_AL_Fault_Number3_45 : 26|9@1+ (1,0) [0|511] ""  MBMU,PC
 SG_ S2A_AL_Fault_Number4_45 : 35|9@1+ (1,0) [0|511] ""  MBMU,PC
 SG_ S2A_AL_Fault_Number5_45 : 44|9@1+ (1,0) [0|511] ""  MBMU,PC
 SG_ S2A_AL_Fault_Number6_45 : 53|9@1+ (1,0) [0|511] ""  MBMU,PC

BO_ 2265055086 S2A_ALARM__46: 8 SBMU
 SG_ S2A_AL_Fault_Page_46 : 0|8@1+ (1,0) [0|255] ""  MBMU,PC
 SG_ S2A_AL_Fault_Number1_46 : 8|9@1+ (1,0) [0|511] ""  MBMU,PC
 SG_ S2A_AL_Fault_Number2_46 : 17|9@1+ (1,0) [0|511] ""  MBMU,PC
 SG_ S2A_AL_Fault_Number3_46 : 26|9@1+ (1,0) [0|511] ""  MBMU,PC
 SG_ S2A_AL_Fault_Number4_46 : 35|9@1+ (1,0) [0|511] ""  MBMU,PC
 SG_ S2A_AL_Fault_Number5_46 : 44|9@1+ (1,0) [0|511] ""  MBMU,PC
 SG_ S2A_AL_Fault_Number6_46 : 53|9@1+ (1,0) [0|511] ""  MBMU,PC

BO_ 2265055087 S2A_ALARM__47: 8 SBMU
 SG_ S2A_AL_Fault_Page_47 : 0|8@1+ (1,0) [0|255] ""  MBMU,PC
 SG_ S2A_AL_Fault_Number1_47 : 8|9@1+ (1,0) [0|511] ""  MBMU,PC
 SG_ S2A_AL_Fault_Number2_47 : 17|9@1+ (1,0) [0|511] ""  MBMU,PC
 SG_ S2A_AL_Fault_Number3_47 : 26|9@1+ (1,0) [0|511] ""  MBMU,PC
 SG_ S2A_AL_Fault_Number4_47 : 35|9@1+ (1,0) [0|511] ""  MBMU,PC
 SG_ S2A_AL_Fault_Number5_47 : 44|9@1+ (1,0) [0|511] ""  MBMU,PC
 SG_ S2A_AL_Fault_Number6_47 : 53|9@1+ (1,0) [0|511] ""  MBMU,PC

BO_ 2265055088 S2A_ALARM__48: 8 SBMU
 SG_ S2A_AL_Fault_Page_48 : 0|8@1+ (1,0) [0|255] ""  MBMU,PC
 SG_ S2A_AL_Fault_Number1_48 : 8|9@1+ (1,0) [0|511] ""  MBMU,PC
 SG_ S2A_AL_Fault_Number2_48 : 17|9@1+ (1,0) [0|511] ""  MBMU,PC
 SG_ S2A_AL_Fault_Number3_48 : 26|9@1+ (1,0) [0|511] ""  MBMU,PC
 SG_ S2A_AL_Fault_Number4_48 : 35|9@1+ (1,0) [0|511] ""  MBMU,PC
 SG_ S2A_AL_Fault_Number5_48 : 44|9@1+ (1,0) [0|511] ""  MBMU,PC
 SG_ S2A_AL_Fault_Number6_48 : 53|9@1+ (1,0) [0|511] ""  MBMU,PC

BO_ 2265055089 S2A_ALARM__49: 8 SBMU
 SG_ S2A_AL_Fault_Page_49 : 0|8@1+ (1,0) [0|255] ""  MBMU,PC
 SG_ S2A_AL_Fault_Number1_49 : 8|9@1+ (1,0) [0|511] ""  MBMU,PC
 SG_ S2A_AL_Fault_Number2_49 : 17|9@1+ (1,0) [0|511] ""  MBMU,PC
 SG_ S2A_AL_Fault_Number3_49 : 26|9@1+ (1,0) [0|511] ""  MBMU,PC
 SG_ S2A_AL_Fault_Number4_49 : 35|9@1+ (1,0) [0|511] ""  MBMU,PC
 SG_ S2A_AL_Fault_Number5_49 : 44|9@1+ (1,0) [0|511] ""  MBMU,PC
 SG_ S2A_AL_Fault_Number6_49 : 53|9@1+ (1,0) [0|511] ""  MBMU,PC

BO_ 2265055090 S2A_ALARM__50: 8 SBMU
 SG_ S2A_AL_Fault_Page_50 : 0|8@1+ (1,0) [0|255] ""  MBMU,PC
 SG_ S2A_AL_Fault_Number1_50 : 8|9@1+ (1,0) [0|511] ""  MBMU,PC
 SG_ S2A_AL_Fault_Number2_50 : 17|9@1+ (1,0) [0|511] ""  MBMU,PC
 SG_ S2A_AL_Fault_Number3_50 : 26|9@1+ (1,0) [0|511] ""  MBMU,PC
 SG_ S2A_AL_Fault_Number4_50 : 35|9@1+ (1,0) [0|511] ""  MBMU,PC
 SG_ S2A_AL_Fault_Number5_50 : 44|9@1+ (1,0) [0|511] ""  MBMU,PC
 SG_ S2A_AL_Fault_Number6_50 : 53|9@1+ (1,0) [0|511] ""  MBMU,PC

BO_ 2265055091 S2A_ALARM__51: 8 SBMU
 SG_ S2A_AL_Fault_Page_51 : 0|8@1+ (1,0) [0|255] ""  MBMU,PC
 SG_ S2A_AL_Fault_Number1_51 : 8|9@1+ (1,0) [0|511] ""  MBMU,PC
 SG_ S2A_AL_Fault_Number2_51 : 17|9@1+ (1,0) [0|511] ""  MBMU,PC
 SG_ S2A_AL_Fault_Number3_51 : 26|9@1+ (1,0) [0|511] ""  MBMU,PC
 SG_ S2A_AL_Fault_Number4_51 : 35|9@1+ (1,0) [0|511] ""  MBMU,PC
 SG_ S2A_AL_Fault_Number5_51 : 44|9@1+ (1,0) [0|511] ""  MBMU,PC
 SG_ S2A_AL_Fault_Number6_51 : 53|9@1+ (1,0) [0|511] ""  MBMU,PC

BO_ 2265055092 S2A_ALARM__52: 8 SBMU
 SG_ S2A_AL_Fault_Page_52 : 0|8@1+ (1,0) [0|255] ""  MBMU,PC
 SG_ S2A_AL_Fault_Number1_52 : 8|9@1+ (1,0) [0|511] ""  MBMU,PC
 SG_ S2A_AL_Fault_Number2_52 : 17|9@1+ (1,0) [0|511] ""  MBMU,PC
 SG_ S2A_AL_Fault_Number3_52 : 26|9@1+ (1,0) [0|511] ""  MBMU,PC
 SG_ S2A_AL_Fault_Number4_52 : 35|9@1+ (1,0) [0|511] ""  MBMU,PC
 SG_ S2A_AL_Fault_Number5_52 : 44|9@1+ (1,0) [0|511] ""  MBMU,PC
 SG_ S2A_AL_Fault_Number6_52 : 53|9@1+ (1,0) [0|511] ""  MBMU,PC

BO_ 2265055093 S2A_ALARM__53: 8 SBMU
 SG_ S2A_AL_Fault_Page_53 : 0|8@1+ (1,0) [0|255] ""  MBMU,PC
 SG_ S2A_AL_Fault_Number1_53 : 8|9@1+ (1,0) [0|511] ""  MBMU,PC
 SG_ S2A_AL_Fault_Number2_53 : 17|9@1+ (1,0) [0|511] ""  MBMU,PC
 SG_ S2A_AL_Fault_Number3_53 : 26|9@1+ (1,0) [0|511] ""  MBMU,PC
 SG_ S2A_AL_Fault_Number4_53 : 35|9@1+ (1,0) [0|511] ""  MBMU,PC
 SG_ S2A_AL_Fault_Number5_53 : 44|9@1+ (1,0) [0|511] ""  MBMU,PC
 SG_ S2A_AL_Fault_Number6_53 : 53|9@1+ (1,0) [0|511] ""  MBMU,PC

BO_ 2265055094 S2A_ALARM__54: 8 SBMU
 SG_ S2A_AL_Fault_Page_54 : 0|8@1+ (1,0) [0|255] ""  MBMU,PC
 SG_ S2A_AL_Fault_Number1_54 : 8|9@1+ (1,0) [0|511] ""  MBMU,PC
 SG_ S2A_AL_Fault_Number2_54 : 17|9@1+ (1,0) [0|511] ""  MBMU,PC
 SG_ S2A_AL_Fault_Number3_54 : 26|9@1+ (1,0) [0|511] ""  MBMU,PC
 SG_ S2A_AL_Fault_Number4_54 : 35|9@1+ (1,0) [0|511] ""  MBMU,PC
 SG_ S2A_AL_Fault_Number5_54 : 44|9@1+ (1,0) [0|511] ""  MBMU,PC
 SG_ S2A_AL_Fault_Number6_54 : 53|9@1+ (1,0) [0|511] ""  MBMU,PC

BO_ 2265055095 S2A_ALARM__55: 8 SBMU
 SG_ S2A_AL_Fault_Page_55 : 0|8@1+ (1,0) [0|255] ""  MBMU,PC
 SG_ S2A_AL_Fault_Number1_55 : 8|9@1+ (1,0) [0|511] ""  MBMU,PC
 SG_ S2A_AL_Fault_Number2_55 : 17|9@1+ (1,0) [0|511] ""  MBMU,PC
 SG_ S2A_AL_Fault_Number3_55 : 26|9@1+ (1,0) [0|511] ""  MBMU,PC
 SG_ S2A_AL_Fault_Number4_55 : 35|9@1+ (1,0) [0|511] ""  MBMU,PC
 SG_ S2A_AL_Fault_Number5_55 : 44|9@1+ (1,0) [0|511] ""  MBMU,PC
 SG_ S2A_AL_Fault_Number6_55 : 53|9@1+ (1,0) [0|511] ""  MBMU,PC

BO_ 2265055096 S2A_ALARM__56: 8 SBMU
 SG_ S2A_AL_Fault_Page_56 : 0|8@1+ (1,0) [0|255] ""  MBMU,PC
 SG_ S2A_AL_Fault_Number1_56 : 8|9@1+ (1,0) [0|511] ""  MBMU,PC
 SG_ S2A_AL_Fault_Number2_56 : 17|9@1+ (1,0) [0|511] ""  MBMU,PC
 SG_ S2A_AL_Fault_Number3_56 : 26|9@1+ (1,0) [0|511] ""  MBMU,PC
 SG_ S2A_AL_Fault_Number4_56 : 35|9@1+ (1,0) [0|511] ""  MBMU,PC
 SG_ S2A_AL_Fault_Number5_56 : 44|9@1+ (1,0) [0|511] ""  MBMU,PC
 SG_ S2A_AL_Fault_Number6_56 : 53|9@1+ (1,0) [0|511] ""  MBMU,PC

BO_ 2265055097 S2A_ALARM__57: 8 SBMU
 SG_ S2A_AL_Fault_Page_57 : 0|8@1+ (1,0) [0|255] ""  MBMU,PC
 SG_ S2A_AL_Fault_Number1_57 : 8|9@1+ (1,0) [0|511] ""  MBMU,PC
 SG_ S2A_AL_Fault_Number2_57 : 17|9@1+ (1,0) [0|511] ""  MBMU,PC
 SG_ S2A_AL_Fault_Number3_57 : 26|9@1+ (1,0) [0|511] ""  MBMU,PC
 SG_ S2A_AL_Fault_Number4_57 : 35|9@1+ (1,0) [0|511] ""  MBMU,PC
 SG_ S2A_AL_Fault_Number5_57 : 44|9@1+ (1,0) [0|511] ""  MBMU,PC
 SG_ S2A_AL_Fault_Number6_57 : 53|9@1+ (1,0) [0|511] ""  MBMU,PC

BO_ 2265055098 S2A_ALARM__58: 8 SBMU
 SG_ S2A_AL_Fault_Page_58 : 0|8@1+ (1,0) [0|255] ""  MBMU,PC
 SG_ S2A_AL_Fault_Number1_58 : 8|9@1+ (1,0) [0|511] ""  MBMU,PC
 SG_ S2A_AL_Fault_Number2_58 : 17|9@1+ (1,0) [0|511] ""  MBMU,PC
 SG_ S2A_AL_Fault_Number3_58 : 26|9@1+ (1,0) [0|511] ""  MBMU,PC
 SG_ S2A_AL_Fault_Number4_58 : 35|9@1+ (1,0) [0|511] ""  MBMU,PC
 SG_ S2A_AL_Fault_Number5_58 : 44|9@1+ (1,0) [0|511] ""  MBMU,PC
 SG_ S2A_AL_Fault_Number6_58 : 53|9@1+ (1,0) [0|511] ""  MBMU,PC

BO_ 2265055099 S2A_ALARM__59: 8 SBMU
 SG_ S2A_AL_Fault_Page_59 : 0|8@1+ (1,0) [0|255] ""  MBMU,PC
 SG_ S2A_AL_Fault_Number1_59 : 8|9@1+ (1,0) [0|511] ""  MBMU,PC
 SG_ S2A_AL_Fault_Number2_59 : 17|9@1+ (1,0) [0|511] ""  MBMU,PC
 SG_ S2A_AL_Fault_Number3_59 : 26|9@1+ (1,0) [0|511] ""  MBMU,PC
 SG_ S2A_AL_Fault_Number4_59 : 35|9@1+ (1,0) [0|511] ""  MBMU,PC
 SG_ S2A_AL_Fault_Number5_59 : 44|9@1+ (1,0) [0|511] ""  MBMU,PC
 SG_ S2A_AL_Fault_Number6_59 : 53|9@1+ (1,0) [0|511] ""  MBMU,PC

BO_ 2265055100 S2A_ALARM__60: 8 SBMU
 SG_ S2A_AL_Fault_Page_60 : 0|8@1+ (1,0) [0|255] ""  MBMU,PC
 SG_ S2A_AL_Fault_Number1_60 : 8|9@1+ (1,0) [0|511] ""  MBMU,PC
 SG_ S2A_AL_Fault_Number2_60 : 17|9@1+ (1,0) [0|511] ""  MBMU,PC
 SG_ S2A_AL_Fault_Number3_60 : 26|9@1+ (1,0) [0|511] ""  MBMU,PC
 SG_ S2A_AL_Fault_Number4_60 : 35|9@1+ (1,0) [0|511] ""  MBMU,PC
 SG_ S2A_AL_Fault_Number5_60 : 44|9@1+ (1,0) [0|511] ""  MBMU,PC
 SG_ S2A_AL_Fault_Number6_60 : 53|9@1+ (1,0) [0|511] ""  MBMU,PC

BO_ 2265055101 S2A_ALARM__61: 8 SBMU
 SG_ S2A_AL_Fault_Page_61 : 0|8@1+ (1,0) [0|255] ""  MBMU,PC
 SG_ S2A_AL_Fault_Number1_61 : 8|9@1+ (1,0) [0|511] ""  MBMU,PC
 SG_ S2A_AL_Fault_Number2_61 : 17|9@1+ (1,0) [0|511] ""  MBMU,PC
 SG_ S2A_AL_Fault_Number3_61 : 26|9@1+ (1,0) [0|511] ""  MBMU,PC
 SG_ S2A_AL_Fault_Number4_61 : 35|9@1+ (1,0) [0|511] ""  MBMU,PC
 SG_ S2A_AL_Fault_Number5_61 : 44|9@1+ (1,0) [0|511] ""  MBMU,PC
 SG_ S2A_AL_Fault_Number6_61 : 53|9@1+ (1,0) [0|511] ""  MBMU,PC

BO_ 2265055102 S2A_ALARM__62: 8 SBMU
 SG_ S2A_AL_Fault_Page_62 : 0|8@1+ (1,0) [0|255] ""  MBMU,PC
 SG_ S2A_AL_Fault_Number1_62 : 8|9@1+ (1,0) [0|511] ""  MBMU,PC
 SG_ S2A_AL_Fault_Number2_62 : 17|9@1+ (1,0) [0|511] ""  MBMU,PC
 SG_ S2A_AL_Fault_Number3_62 : 26|9@1+ (1,0) [0|511] ""  MBMU,PC
 SG_ S2A_AL_Fault_Number4_62 : 35|9@1+ (1,0) [0|511] ""  MBMU,PC
 SG_ S2A_AL_Fault_Number5_62 : 44|9@1+ (1,0) [0|511] ""  MBMU,PC
 SG_ S2A_AL_Fault_Number6_62 : 53|9@1+ (1,0) [0|511] ""  MBMU,PC

BO_ 2265055103 S2A_ALARM__63: 8 SBMU
 SG_ S2A_AL_Fault_Page_63 : 0|8@1+ (1,0) [0|255] ""  MBMU,PC
 SG_ S2A_AL_Fault_Number1_63 : 8|9@1+ (1,0) [0|511] ""  MBMU,PC
 SG_ S2A_AL_Fault_Number2_63 : 17|9@1+ (1,0) [0|511] ""  MBMU,PC
 SG_ S2A_AL_Fault_Number3_63 : 26|9@1+ (1,0) [0|511] ""  MBMU,PC
 SG_ S2A_AL_Fault_Number4_63 : 35|9@1+ (1,0) [0|511] ""  MBMU,PC
 SG_ S2A_AL_Fault_Number5_63 : 44|9@1+ (1,0) [0|511] ""  MBMU,PC
 SG_ S2A_AL_Fault_Number6_63 : 53|9@1+ (1,0) [0|511] ""  MBMU,PC

BO_ 2332163905 S2A_SUMDATA1__01: 8 SBMU
 SG_ CRC_S2A_S1_01 : 0|8@1+ (1,0) [0|255] ""  MBMU,PC
 SG_ BAT_U_HVS_01 : 8|16@1+ (0.1,0) [0|6553.5] "V"  MBMU,PC
 SG_ BAT_U_TOT_HVS_01 : 24|16@1+ (0.1,0) [0|6553.5] "V"  MBMU,PC
 SG_ HIS_NumofChg_DisChgCycles_01 : 40|16@1+ (1,0) [0|65535] ""  MBMU,PC
 SG_ BAT_standingstatus_01 : 56|8@1+ (1,0) [0|255] ""  MBMU,PC

BO_ 2332163906 S2A_SUMDATA1__02: 8 SBMU
 SG_ CRC_S2A_S1_02 : 0|8@1+ (1,0) [0|255] ""  MBMU,PC
 SG_ BAT_U_HVS_02 : 8|16@1+ (0.1,0) [0|6553.5] "V"  MBMU,PC
 SG_ BAT_U_TOT_HVS_02 : 24|16@1+ (0.1,0) [0|6553.5] "V"  MBMU,PC
 SG_ HIS_NumofChg_DisChgCycles_02 : 40|16@1+ (1,0) [0|65535] ""  MBMU,PC
 SG_ BAT_standingstatus_02 : 56|8@1+ (1,0) [0|255] ""  MBMU,PC

BO_ 2332163907 S2A_SUMDATA1__03: 8 SBMU
 SG_ CRC_S2A_S1_03 : 0|8@1+ (1,0) [0|255] ""  MBMU,PC
 SG_ BAT_U_HVS_03 : 8|16@1+ (0.1,0) [0|6553.5] "V"  MBMU,PC
 SG_ BAT_U_TOT_HVS_03 : 24|16@1+ (0.1,0) [0|6553.5] "V"  MBMU,PC
 SG_ HIS_NumofChg_DisChgCycles_03 : 40|16@1+ (1,0) [0|65535] ""  MBMU,PC
 SG_ BAT_standingstatus_03 : 56|8@1+ (1,0) [0|255] ""  MBMU,PC

BO_ 2332163908 S2A_SUMDATA1__04: 8 SBMU
 SG_ CRC_S2A_S1_04 : 0|8@1+ (1,0) [0|255] ""  MBMU,PC
 SG_ BAT_U_HVS_04 : 8|16@1+ (0.1,0) [0|6553.5] "V"  MBMU,PC
 SG_ BAT_U_TOT_HVS_04 : 24|16@1+ (0.1,0) [0|6553.5] "V"  MBMU,PC
 SG_ HIS_NumofChg_DisChgCycles_04 : 40|16@1+ (1,0) [0|65535] ""  MBMU,PC
 SG_ BAT_standingstatus_04 : 56|8@1+ (1,0) [0|255] ""  MBMU,PC

BO_ 2332163909 S2A_SUMDATA1__05: 8 SBMU
 SG_ CRC_S2A_S1_05 : 0|8@1+ (1,0) [0|255] ""  MBMU,PC
 SG_ BAT_U_HVS_05 : 8|16@1+ (0.1,0) [0|6553.5] "V"  MBMU,PC
 SG_ BAT_U_TOT_HVS_05 : 24|16@1+ (0.1,0) [0|6553.5] "V"  MBMU,PC
 SG_ HIS_NumofChg_DisChgCycles_05 : 40|16@1+ (1,0) [0|65535] ""  MBMU,PC
 SG_ BAT_standingstatus_05 : 56|8@1+ (1,0) [0|255] ""  MBMU,PC

BO_ 2332163910 S2A_SUMDATA1__06: 8 SBMU
 SG_ CRC_S2A_S1_06 : 0|8@1+ (1,0) [0|255] ""  MBMU,PC
 SG_ BAT_U_HVS_06 : 8|16@1+ (0.1,0) [0|6553.5] "V"  MBMU,PC
 SG_ BAT_U_TOT_HVS_06 : 24|16@1+ (0.1,0) [0|6553.5] "V"  MBMU,PC
 SG_ HIS_NumofChg_DisChgCycles_06 : 40|16@1+ (1,0) [0|65535] ""  MBMU,PC
 SG_ BAT_standingstatus_06 : 56|8@1+ (1,0) [0|255] ""  MBMU,PC

BO_ 2332163911 S2A_SUMDATA1__07: 8 SBMU
 SG_ CRC_S2A_S1_07 : 0|8@1+ (1,0) [0|255] ""  MBMU,PC
 SG_ BAT_U_HVS_07 : 8|16@1+ (0.1,0) [0|6553.5] "V"  MBMU,PC
 SG_ BAT_U_TOT_HVS_07 : 24|16@1+ (0.1,0) [0|6553.5] "V"  MBMU,PC
 SG_ HIS_NumofChg_DisChgCycles_07 : 40|16@1+ (1,0) [0|65535] ""  MBMU,PC
 SG_ BAT_standingstatus_07 : 56|8@1+ (1,0) [0|255] ""  MBMU,PC

BO_ 2332163912 S2A_SUMDATA1__08: 8 SBMU
 SG_ CRC_S2A_S1_08 : 0|8@1+ (1,0) [0|255] ""  MBMU,PC
 SG_ BAT_U_HVS_08 : 8|16@1+ (0.1,0) [0|6553.5] "V"  MBMU,PC
 SG_ BAT_U_TOT_HVS_08 : 24|16@1+ (0.1,0) [0|6553.5] "V"  MBMU,PC
 SG_ HIS_NumofChg_DisChgCycles_08 : 40|16@1+ (1,0) [0|65535] ""  MBMU,PC
 SG_ BAT_standingstatus_08 : 56|8@1+ (1,0) [0|255] ""  MBMU,PC

BO_ 2332163913 S2A_SUMDATA1__09: 8 SBMU
 SG_ CRC_S2A_S1_09 : 0|8@1+ (1,0) [0|255] ""  MBMU,PC
 SG_ BAT_U_HVS_09 : 8|16@1+ (0.1,0) [0|6553.5] "V"  MBMU,PC
 SG_ BAT_U_TOT_HVS_09 : 24|16@1+ (0.1,0) [0|6553.5] "V"  MBMU,PC
 SG_ HIS_NumofChg_DisChgCycles_09 : 40|16@1+ (1,0) [0|65535] ""  MBMU,PC
 SG_ BAT_standingstatus_09 : 56|8@1+ (1,0) [0|255] ""  MBMU,PC

BO_ 2332163914 S2A_SUMDATA1__10: 8 SBMU
 SG_ CRC_S2A_S1_10 : 0|8@1+ (1,0) [0|255] ""  MBMU,PC
 SG_ BAT_U_HVS_10 : 8|16@1+ (0.1,0) [0|6553.5] "V"  MBMU,PC
 SG_ BAT_U_TOT_HVS_10 : 24|16@1+ (0.1,0) [0|6553.5] "V"  MBMU,PC
 SG_ HIS_NumofChg_DisChgCycles_10 : 40|16@1+ (1,0) [0|65535] ""  MBMU,PC
 SG_ BAT_standingstatus_10 : 56|8@1+ (1,0) [0|255] ""  MBMU,PC

BO_ 2332163915 S2A_SUMDATA1__11: 8 SBMU
 SG_ CRC_S2A_S1_11 : 0|8@1+ (1,0) [0|255] ""  MBMU,PC
 SG_ BAT_U_HVS_11 : 8|16@1+ (0.1,0) [0|6553.5] "V"  MBMU,PC
 SG_ BAT_U_TOT_HVS_11 : 24|16@1+ (0.1,0) [0|6553.5] "V"  MBMU,PC
 SG_ HIS_NumofChg_DisChgCycles_11 : 40|16@1+ (1,0) [0|65535] ""  MBMU,PC
 SG_ BAT_standingstatus_11 : 56|8@1+ (1,0) [0|255] ""  MBMU,PC

BO_ 2332163916 S2A_SUMDATA1__12: 8 SBMU
 SG_ CRC_S2A_S1_12 : 0|8@1+ (1,0) [0|255] ""  MBMU,PC
 SG_ BAT_U_HVS_12 : 8|16@1+ (0.1,0) [0|6553.5] "V"  MBMU,PC
 SG_ BAT_U_TOT_HVS_12 : 24|16@1+ (0.1,0) [0|6553.5] "V"  MBMU,PC
 SG_ HIS_NumofChg_DisChgCycles_12 : 40|16@1+ (1,0) [0|65535] ""  MBMU,PC
 SG_ BAT_standingstatus_12 : 56|8@1+ (1,0) [0|255] ""  MBMU,PC

BO_ 2332163917 S2A_SUMDATA1__13: 8 SBMU
 SG_ CRC_S2A_S1_13 : 0|8@1+ (1,0) [0|255] ""  MBMU,PC
 SG_ BAT_U_HVS_13 : 8|16@1+ (0.1,0) [0|6553.5] "V"  MBMU,PC
 SG_ BAT_U_TOT_HVS_13 : 24|16@1+ (0.1,0) [0|6553.5] "V"  MBMU,PC
 SG_ HIS_NumofChg_DisChgCycles_13 : 40|16@1+ (1,0) [0|65535] ""  MBMU,PC
 SG_ BAT_standingstatus_13 : 56|8@1+ (1,0) [0|255] ""  MBMU,PC

BO_ 2332163918 S2A_SUMDATA1__14: 8 SBMU
 SG_ CRC_S2A_S1_14 : 0|8@1+ (1,0) [0|255] ""  MBMU,PC
 SG_ BAT_U_HVS_14 : 8|16@1+ (0.1,0) [0|6553.5] "V"  MBMU,PC
 SG_ BAT_U_TOT_HVS_14 : 24|16@1+ (0.1,0) [0|6553.5] "V"  MBMU,PC
 SG_ HIS_NumofChg_DisChgCycles_14 : 40|16@1+ (1,0) [0|65535] ""  MBMU,PC
 SG_ BAT_standingstatus_14 : 56|8@1+ (1,0) [0|255] ""  MBMU,PC

BO_ 2332163919 S2A_SUMDATA1__15: 8 SBMU
 SG_ CRC_S2A_S1_15 : 0|8@1+ (1,0) [0|255] ""  MBMU,PC
 SG_ BAT_U_HVS_15 : 8|16@1+ (0.1,0) [0|6553.5] "V"  MBMU,PC
 SG_ BAT_U_TOT_HVS_15 : 24|16@1+ (0.1,0) [0|6553.5] "V"  MBMU,PC
 SG_ HIS_NumofChg_DisChgCycles_15 : 40|16@1+ (1,0) [0|65535] ""  MBMU,PC
 SG_ BAT_standingstatus_15 : 56|8@1+ (1,0) [0|255] ""  MBMU,PC

BO_ 2332163920 S2A_SUMDATA1__16: 8 SBMU
 SG_ CRC_S2A_S1_16 : 0|8@1+ (1,0) [0|255] ""  MBMU,PC
 SG_ BAT_U_HVS_16 : 8|16@1+ (0.1,0) [0|6553.5] "V"  MBMU,PC
 SG_ BAT_U_TOT_HVS_16 : 24|16@1+ (0.1,0) [0|6553.5] "V"  MBMU,PC
 SG_ HIS_NumofChg_DisChgCycles_16 : 40|16@1+ (1,0) [0|65535] ""  MBMU,PC
 SG_ BAT_standingstatus_16 : 56|8@1+ (1,0) [0|255] ""  MBMU,PC

BO_ 2332163921 S2A_SUMDATA1__17: 8 SBMU
 SG_ CRC_S2A_S1_17 : 0|8@1+ (1,0) [0|255] ""  MBMU,PC
 SG_ BAT_U_HVS_17 : 8|16@1+ (0.1,0) [0|6553.5] "V"  MBMU,PC
 SG_ BAT_U_TOT_HVS_17 : 24|16@1+ (0.1,0) [0|6553.5] "V"  MBMU,PC
 SG_ HIS_NumofChg_DisChgCycles_17 : 40|16@1+ (1,0) [0|65535] ""  MBMU,PC
 SG_ BAT_standingstatus_17 : 56|8@1+ (1,0) [0|255] ""  MBMU,PC

BO_ 2332163922 S2A_SUMDATA1__18: 8 SBMU
 SG_ CRC_S2A_S1_18 : 0|8@1+ (1,0) [0|255] ""  MBMU,PC
 SG_ BAT_U_HVS_18 : 8|16@1+ (0.1,0) [0|6553.5] "V"  MBMU,PC
 SG_ BAT_U_TOT_HVS_18 : 24|16@1+ (0.1,0) [0|6553.5] "V"  MBMU,PC
 SG_ HIS_NumofChg_DisChgCycles_18 : 40|16@1+ (1,0) [0|65535] ""  MBMU,PC
 SG_ BAT_standingstatus_18 : 56|8@1+ (1,0) [0|255] ""  MBMU,PC

BO_ 2332163923 S2A_SUMDATA1__19: 8 SBMU
 SG_ CRC_S2A_S1_19 : 0|8@1+ (1,0) [0|255] ""  MBMU,PC
 SG_ BAT_U_HVS_19 : 8|16@1+ (0.1,0) [0|6553.5] "V"  MBMU,PC
 SG_ BAT_U_TOT_HVS_19 : 24|16@1+ (0.1,0) [0|6553.5] "V"  MBMU,PC
 SG_ HIS_NumofChg_DisChgCycles_19 : 40|16@1+ (1,0) [0|65535] ""  MBMU,PC
 SG_ BAT_standingstatus_19 : 56|8@1+ (1,0) [0|255] ""  MBMU,PC

BO_ 2332163924 S2A_SUMDATA1__20: 8 SBMU
 SG_ CRC_S2A_S1_20 : 0|8@1+ (1,0) [0|255] ""  MBMU,PC
 SG_ BAT_U_HVS_20 : 8|16@1+ (0.1,0) [0|6553.5] "V"  MBMU,PC
 SG_ BAT_U_TOT_HVS_20 : 24|16@1+ (0.1,0) [0|6553.5] "V"  MBMU,PC
 SG_ HIS_NumofChg_DisChgCycles_20 : 40|16@1+ (1,0) [0|65535] ""  MBMU,PC
 SG_ BAT_standingstatus_20 : 56|8@1+ (1,0) [0|255] ""  MBMU,PC

BO_ 2332163925 S2A_SUMDATA1__21: 8 SBMU
 SG_ CRC_S2A_S1_21 : 0|8@1+ (1,0) [0|255] ""  MBMU,PC
 SG_ BAT_U_HVS_21 : 8|16@1+ (0.1,0) [0|6553.5] "V"  MBMU,PC
 SG_ BAT_U_TOT_HVS_21 : 24|16@1+ (0.1,0) [0|6553.5] "V"  MBMU,PC
 SG_ HIS_NumofChg_DisChgCycles_21 : 40|16@1+ (1,0) [0|65535] ""  MBMU,PC
 SG_ BAT_standingstatus_21 : 56|8@1+ (1,0) [0|255] ""  MBMU,PC

BO_ 2332163926 S2A_SUMDATA1__22: 8 SBMU
 SG_ CRC_S2A_S1_22 : 0|8@1+ (1,0) [0|255] ""  MBMU,PC
 SG_ BAT_U_HVS_22 : 8|16@1+ (0.1,0) [0|6553.5] "V"  MBMU,PC
 SG_ BAT_U_TOT_HVS_22 : 24|16@1+ (0.1,0) [0|6553.5] "V"  MBMU,PC
 SG_ HIS_NumofChg_DisChgCycles_22 : 40|16@1+ (1,0) [0|65535] ""  MBMU,PC
 SG_ BAT_standingstatus_22 : 56|8@1+ (1,0) [0|255] ""  MBMU,PC

BO_ 2332163927 S2A_SUMDATA1__23: 8 SBMU
 SG_ CRC_S2A_S1_23 : 0|8@1+ (1,0) [0|255] ""  MBMU,PC
 SG_ BAT_U_HVS_23 : 8|16@1+ (0.1,0) [0|6553.5] "V"  MBMU,PC
 SG_ BAT_U_TOT_HVS_23 : 24|16@1+ (0.1,0) [0|6553.5] "V"  MBMU,PC
 SG_ HIS_NumofChg_DisChgCycles_23 : 40|16@1+ (1,0) [0|65535] ""  MBMU,PC
 SG_ BAT_standingstatus_23 : 56|8@1+ (1,0) [0|255] ""  MBMU,PC

BO_ 2332163928 S2A_SUMDATA1__24: 8 SBMU
 SG_ CRC_S2A_S1_24 : 0|8@1+ (1,0) [0|255] ""  MBMU,PC
 SG_ BAT_U_HVS_24 : 8|16@1+ (0.1,0) [0|6553.5] "V"  MBMU,PC
 SG_ BAT_U_TOT_HVS_24 : 24|16@1+ (0.1,0) [0|6553.5] "V"  MBMU,PC
 SG_ HIS_NumofChg_DisChgCycles_24 : 40|16@1+ (1,0) [0|65535] ""  MBMU,PC
 SG_ BAT_standingstatus_24 : 56|8@1+ (1,0) [0|255] ""  MBMU,PC

BO_ 2332163929 S2A_SUMDATA1__25: 8 SBMU
 SG_ CRC_S2A_S1_25 : 0|8@1+ (1,0) [0|255] ""  MBMU,PC
 SG_ BAT_U_HVS_25 : 8|16@1+ (0.1,0) [0|6553.5] "V"  MBMU,PC
 SG_ BAT_U_TOT_HVS_25 : 24|16@1+ (0.1,0) [0|6553.5] "V"  MBMU,PC
 SG_ HIS_NumofChg_DisChgCycles_25 : 40|16@1+ (1,0) [0|65535] ""  MBMU,PC
 SG_ BAT_standingstatus_25 : 56|8@1+ (1,0) [0|255] ""  MBMU,PC

BO_ 2332163930 S2A_SUMDATA1__26: 8 SBMU
 SG_ CRC_S2A_S1_26 : 0|8@1+ (1,0) [0|255] ""  MBMU,PC
 SG_ BAT_U_HVS_26 : 8|16@1+ (0.1,0) [0|6553.5] "V"  MBMU,PC
 SG_ BAT_U_TOT_HVS_26 : 24|16@1+ (0.1,0) [0|6553.5] "V"  MBMU,PC
 SG_ HIS_NumofChg_DisChgCycles_26 : 40|16@1+ (1,0) [0|65535] ""  MBMU,PC
 SG_ BAT_standingstatus_26 : 56|8@1+ (1,0) [0|255] ""  MBMU,PC

BO_ 2332163931 S2A_SUMDATA1__27: 8 SBMU
 SG_ CRC_S2A_S1_27 : 0|8@1+ (1,0) [0|255] ""  MBMU,PC
 SG_ BAT_U_HVS_27 : 8|16@1+ (0.1,0) [0|6553.5] "V"  MBMU,PC
 SG_ BAT_U_TOT_HVS_27 : 24|16@1+ (0.1,0) [0|6553.5] "V"  MBMU,PC
 SG_ HIS_NumofChg_DisChgCycles_27 : 40|16@1+ (1,0) [0|65535] ""  MBMU,PC
 SG_ BAT_standingstatus_27 : 56|8@1+ (1,0) [0|255] ""  MBMU,PC

BO_ 2332163932 S2A_SUMDATA1__28: 8 SBMU
 SG_ CRC_S2A_S1_28 : 0|8@1+ (1,0) [0|255] ""  MBMU,PC
 SG_ BAT_U_HVS_28 : 8|16@1+ (0.1,0) [0|6553.5] "V"  MBMU,PC
 SG_ BAT_U_TOT_HVS_28 : 24|16@1+ (0.1,0) [0|6553.5] "V"  MBMU,PC
 SG_ HIS_NumofChg_DisChgCycles_28 : 40|16@1+ (1,0) [0|65535] ""  MBMU,PC
 SG_ BAT_standingstatus_28 : 56|8@1+ (1,0) [0|255] ""  MBMU,PC

BO_ 2332163933 S2A_SUMDATA1__29: 8 SBMU
 SG_ CRC_S2A_S1_29 : 0|8@1+ (1,0) [0|255] ""  MBMU,PC
 SG_ BAT_U_HVS_29 : 8|16@1+ (0.1,0) [0|6553.5] "V"  MBMU,PC
 SG_ BAT_U_TOT_HVS_29 : 24|16@1+ (0.1,0) [0|6553.5] "V"  MBMU,PC
 SG_ HIS_NumofChg_DisChgCycles_29 : 40|16@1+ (1,0) [0|65535] ""  MBMU,PC
 SG_ BAT_standingstatus_29 : 56|8@1+ (1,0) [0|255] ""  MBMU,PC

BO_ 2332163934 S2A_SUMDATA1__30: 8 SBMU
 SG_ CRC_S2A_S1_30 : 0|8@1+ (1,0) [0|255] ""  MBMU,PC
 SG_ BAT_U_HVS_30 : 8|16@1+ (0.1,0) [0|6553.5] "V"  MBMU,PC
 SG_ BAT_U_TOT_HVS_30 : 24|16@1+ (0.1,0) [0|6553.5] "V"  MBMU,PC
 SG_ HIS_NumofChg_DisChgCycles_30 : 40|16@1+ (1,0) [0|65535] ""  MBMU,PC
 SG_ BAT_standingstatus_30 : 56|8@1+ (1,0) [0|255] ""  MBMU,PC

BO_ 2332163935 S2A_SUMDATA1__31: 8 SBMU
 SG_ CRC_S2A_S1_31 : 0|8@1+ (1,0) [0|255] ""  MBMU,PC
 SG_ BAT_U_HVS_31 : 8|16@1+ (0.1,0) [0|6553.5] "V"  MBMU,PC
 SG_ BAT_U_TOT_HVS_31 : 24|16@1+ (0.1,0) [0|6553.5] "V"  MBMU,PC
 SG_ HIS_NumofChg_DisChgCycles_31 : 40|16@1+ (1,0) [0|65535] ""  MBMU,PC
 SG_ BAT_standingstatus_31 : 56|8@1+ (1,0) [0|255] ""  MBMU,PC

BO_ 2332163936 S2A_SUMDATA1__32: 8 SBMU
 SG_ CRC_S2A_S1_32 : 0|8@1+ (1,0) [0|255] ""  MBMU,PC
 SG_ BAT_U_HVS_32 : 8|16@1+ (0.1,0) [0|6553.5] "V"  MBMU,PC
 SG_ BAT_U_TOT_HVS_32 : 24|16@1+ (0.1,0) [0|6553.5] "V"  MBMU,PC
 SG_ HIS_NumofChg_DisChgCycles_32 : 40|16@1+ (1,0) [0|65535] ""  MBMU,PC
 SG_ BAT_standingstatus_32 : 56|8@1+ (1,0) [0|255] ""  MBMU,PC

BO_ 2332163937 S2A_SUMDATA1__33: 8 SBMU
 SG_ CRC_S2A_S1_33 : 0|8@1+ (1,0) [0|255] ""  MBMU,PC
 SG_ BAT_U_HVS_33 : 8|16@1+ (0.1,0) [0|6553.5] "V"  MBMU,PC
 SG_ BAT_U_TOT_HVS_33 : 24|16@1+ (0.1,0) [0|6553.5] "V"  MBMU,PC
 SG_ HIS_NumofChg_DisChgCycles_33 : 40|16@1+ (1,0) [0|65535] ""  MBMU,PC
 SG_ BAT_standingstatus_33 : 56|8@1+ (1,0) [0|255] ""  MBMU,PC

BO_ 2332163938 S2A_SUMDATA1__34: 8 SBMU
 SG_ CRC_S2A_S1_34 : 0|8@1+ (1,0) [0|255] ""  MBMU,PC
 SG_ BAT_U_HVS_34 : 8|16@1+ (0.1,0) [0|6553.5] "V"  MBMU,PC
 SG_ BAT_U_TOT_HVS_34 : 24|16@1+ (0.1,0) [0|6553.5] "V"  MBMU,PC
 SG_ HIS_NumofChg_DisChgCycles_34 : 40|16@1+ (1,0) [0|65535] ""  MBMU,PC
 SG_ BAT_standingstatus_34 : 56|8@1+ (1,0) [0|255] ""  MBMU,PC

BO_ 2332163939 S2A_SUMDATA1__35: 8 SBMU
 SG_ CRC_S2A_S1_35 : 0|8@1+ (1,0) [0|255] ""  MBMU,PC
 SG_ BAT_U_HVS_35 : 8|16@1+ (0.1,0) [0|6553.5] "V"  MBMU,PC
 SG_ BAT_U_TOT_HVS_35 : 24|16@1+ (0.1,0) [0|6553.5] "V"  MBMU,PC
 SG_ HIS_NumofChg_DisChgCycles_35 : 40|16@1+ (1,0) [0|65535] ""  MBMU,PC
 SG_ BAT_standingstatus_35 : 56|8@1+ (1,0) [0|255] ""  MBMU,PC

BO_ 2332163940 S2A_SUMDATA1__36: 8 SBMU
 SG_ CRC_S2A_S1_36 : 0|8@1+ (1,0) [0|255] ""  MBMU,PC
 SG_ BAT_U_HVS_36 : 8|16@1+ (0.1,0) [0|6553.5] "V"  MBMU,PC
 SG_ BAT_U_TOT_HVS_36 : 24|16@1+ (0.1,0) [0|6553.5] "V"  MBMU,PC
 SG_ HIS_NumofChg_DisChgCycles_36 : 40|16@1+ (1,0) [0|65535] ""  MBMU,PC
 SG_ BAT_standingstatus_36 : 56|8@1+ (1,0) [0|255] ""  MBMU,PC

BO_ 2332163941 S2A_SUMDATA1__37: 8 SBMU
 SG_ CRC_S2A_S1_37 : 0|8@1+ (1,0) [0|255] ""  MBMU,PC
 SG_ BAT_U_HVS_37 : 8|16@1+ (0.1,0) [0|6553.5] "V"  MBMU,PC
 SG_ BAT_U_TOT_HVS_37 : 24|16@1+ (0.1,0) [0|6553.5] "V"  MBMU,PC
 SG_ HIS_NumofChg_DisChgCycles_37 : 40|16@1+ (1,0) [0|65535] ""  MBMU,PC
 SG_ BAT_standingstatus_37 : 56|8@1+ (1,0) [0|255] ""  MBMU,PC

BO_ 2332163942 S2A_SUMDATA1__38: 8 SBMU
 SG_ CRC_S2A_S1_38 : 0|8@1+ (1,0) [0|255] ""  MBMU,PC
 SG_ BAT_U_HVS_38 : 8|16@1+ (0.1,0) [0|6553.5] "V"  MBMU,PC
 SG_ BAT_U_TOT_HVS_38 : 24|16@1+ (0.1,0) [0|6553.5] "V"  MBMU,PC
 SG_ HIS_NumofChg_DisChgCycles_38 : 40|16@1+ (1,0) [0|65535] ""  MBMU,PC
 SG_ BAT_standingstatus_38 : 56|8@1+ (1,0) [0|255] ""  MBMU,PC

BO_ 2332163943 S2A_SUMDATA1__39: 8 SBMU
 SG_ CRC_S2A_S1_39 : 0|8@1+ (1,0) [0|255] ""  MBMU,PC
 SG_ BAT_U_HVS_39 : 8|16@1+ (0.1,0) [0|6553.5] "V"  MBMU,PC
 SG_ BAT_U_TOT_HVS_39 : 24|16@1+ (0.1,0) [0|6553.5] "V"  MBMU,PC
 SG_ HIS_NumofChg_DisChgCycles_39 : 40|16@1+ (1,0) [0|65535] ""  MBMU,PC
 SG_ BAT_standingstatus_39 : 56|8@1+ (1,0) [0|255] ""  MBMU,PC

BO_ 2332163944 S2A_SUMDATA1__40: 8 SBMU
 SG_ CRC_S2A_S1_40 : 0|8@1+ (1,0) [0|255] ""  MBMU,PC
 SG_ BAT_U_HVS_40 : 8|16@1+ (0.1,0) [0|6553.5] "V"  MBMU,PC
 SG_ BAT_U_TOT_HVS_40 : 24|16@1+ (0.1,0) [0|6553.5] "V"  MBMU,PC
 SG_ HIS_NumofChg_DisChgCycles_40 : 40|16@1+ (1,0) [0|65535] ""  MBMU,PC
 SG_ BAT_standingstatus_40 : 56|8@1+ (1,0) [0|255] ""  MBMU,PC

BO_ 2332163945 S2A_SUMDATA1__41: 8 SBMU
 SG_ CRC_S2A_S1_41 : 0|8@1+ (1,0) [0|255] ""  MBMU,PC
 SG_ BAT_U_HVS_41 : 8|16@1+ (0.1,0) [0|6553.5] "V"  MBMU,PC
 SG_ BAT_U_TOT_HVS_41 : 24|16@1+ (0.1,0) [0|6553.5] "V"  MBMU,PC
 SG_ HIS_NumofChg_DisChgCycles_41 : 40|16@1+ (1,0) [0|65535] ""  MBMU,PC
 SG_ BAT_standingstatus_41 : 56|8@1+ (1,0) [0|255] ""  MBMU,PC

BO_ 2332163946 S2A_SUMDATA1__42: 8 SBMU
 SG_ CRC_S2A_S1_42 : 0|8@1+ (1,0) [0|255] ""  MBMU,PC
 SG_ BAT_U_HVS_42 : 8|16@1+ (0.1,0) [0|6553.5] "V"  MBMU,PC
 SG_ BAT_U_TOT_HVS_42 : 24|16@1+ (0.1,0) [0|6553.5] "V"  MBMU,PC
 SG_ HIS_NumofChg_DisChgCycles_42 : 40|16@1+ (1,0) [0|65535] ""  MBMU,PC
 SG_ BAT_standingstatus_42 : 56|8@1+ (1,0) [0|255] ""  MBMU,PC

BO_ 2332163947 S2A_SUMDATA1__43: 8 SBMU
 SG_ CRC_S2A_S1_43 : 0|8@1+ (1,0) [0|255] ""  MBMU,PC
 SG_ BAT_U_HVS_43 : 8|16@1+ (0.1,0) [0|6553.5] "V"  MBMU,PC
 SG_ BAT_U_TOT_HVS_43 : 24|16@1+ (0.1,0) [0|6553.5] "V"  MBMU,PC
 SG_ HIS_NumofChg_DisChgCycles_43 : 40|16@1+ (1,0) [0|65535] ""  MBMU,PC
 SG_ BAT_standingstatus_43 : 56|8@1+ (1,0) [0|255] ""  MBMU,PC

BO_ 2332163948 S2A_SUMDATA1__44: 8 SBMU
 SG_ CRC_S2A_S1_44 : 0|8@1+ (1,0) [0|255] ""  MBMU,PC
 SG_ BAT_U_HVS_44 : 8|16@1+ (0.1,0) [0|6553.5] "V"  MBMU,PC
 SG_ BAT_U_TOT_HVS_44 : 24|16@1+ (0.1,0) [0|6553.5] "V"  MBMU,PC
 SG_ HIS_NumofChg_DisChgCycles_44 : 40|16@1+ (1,0) [0|65535] ""  MBMU,PC
 SG_ BAT_standingstatus_44 : 56|8@1+ (1,0) [0|255] ""  MBMU,PC

BO_ 2332163949 S2A_SUMDATA1__45: 8 SBMU
 SG_ CRC_S2A_S1_45 : 0|8@1+ (1,0) [0|255] ""  MBMU,PC
 SG_ BAT_U_HVS_45 : 8|16@1+ (0.1,0) [0|6553.5] "V"  MBMU,PC
 SG_ BAT_U_TOT_HVS_45 : 24|16@1+ (0.1,0) [0|6553.5] "V"  MBMU,PC
 SG_ HIS_NumofChg_DisChgCycles_45 : 40|16@1+ (1,0) [0|65535] ""  MBMU,PC
 SG_ BAT_standingstatus_45 : 56|8@1+ (1,0) [0|255] ""  MBMU,PC

BO_ 2332163950 S2A_SUMDATA1__46: 8 SBMU
 SG_ CRC_S2A_S1_46 : 0|8@1+ (1,0) [0|255] ""  MBMU,PC
 SG_ BAT_U_HVS_46 : 8|16@1+ (0.1,0) [0|6553.5] "V"  MBMU,PC
 SG_ BAT_U_TOT_HVS_46 : 24|16@1+ (0.1,0) [0|6553.5] "V"  MBMU,PC
 SG_ HIS_NumofChg_DisChgCycles_46 : 40|16@1+ (1,0) [0|65535] ""  MBMU,PC
 SG_ BAT_standingstatus_46 : 56|8@1+ (1,0) [0|255] ""  MBMU,PC

BO_ 2332163951 S2A_SUMDATA1__47: 8 SBMU
 SG_ CRC_S2A_S1_47 : 0|8@1+ (1,0) [0|255] ""  MBMU,PC
 SG_ BAT_U_HVS_47 : 8|16@1+ (0.1,0) [0|6553.5] "V"  MBMU,PC
 SG_ BAT_U_TOT_HVS_47 : 24|16@1+ (0.1,0) [0|6553.5] "V"  MBMU,PC
 SG_ HIS_NumofChg_DisChgCycles_47 : 40|16@1+ (1,0) [0|65535] ""  MBMU,PC
 SG_ BAT_standingstatus_47 : 56|8@1+ (1,0) [0|255] ""  MBMU,PC

BO_ 2332163952 S2A_SUMDATA1__48: 8 SBMU
 SG_ CRC_S2A_S1_48 : 0|8@1+ (1,0) [0|255] ""  MBMU,PC
 SG_ BAT_U_HVS_48 : 8|16@1+ (0.1,0) [0|6553.5] "V"  MBMU,PC
 SG_ BAT_U_TOT_HVS_48 : 24|16@1+ (0.1,0) [0|6553.5] "V"  MBMU,PC
 SG_ HIS_NumofChg_DisChgCycles_48 : 40|16@1+ (1,0) [0|65535] ""  MBMU,PC
 SG_ BAT_standingstatus_48 : 56|8@1+ (1,0) [0|255] ""  MBMU,PC

BO_ 2332163953 S2A_SUMDATA1__49: 8 SBMU
 SG_ CRC_S2A_S1_49 : 0|8@1+ (1,0) [0|255] ""  MBMU,PC
 SG_ BAT_U_HVS_49 : 8|16@1+ (0.1,0) [0|6553.5] "V"  MBMU,PC
 SG_ BAT_U_TOT_HVS_49 : 24|16@1+ (0.1,0) [0|6553.5] "V"  MBMU,PC
 SG_ HIS_NumofChg_DisChgCycles_49 : 40|16@1+ (1,0) [0|65535] ""  MBMU,PC
 SG_ BAT_standingstatus_49 : 56|8@1+ (1,0) [0|255] ""  MBMU,PC

BO_ 2332163954 S2A_SUMDATA1__50: 8 SBMU
 SG_ CRC_S2A_S1_50 : 0|8@1+ (1,0) [0|255] ""  MBMU,PC
 SG_ BAT_U_HVS_50 : 8|16@1+ (0.1,0) [0|6553.5] "V"  MBMU,PC
 SG_ BAT_U_TOT_HVS_50 : 24|16@1+ (0.1,0) [0|6553.5] "V"  MBMU,PC
 SG_ HIS_NumofChg_DisChgCycles_50 : 40|16@1+ (1,0) [0|65535] ""  MBMU,PC
 SG_ BAT_standingstatus_50 : 56|8@1+ (1,0) [0|255] ""  MBMU,PC

BO_ 2332163955 S2A_SUMDATA1__51: 8 SBMU
 SG_ CRC_S2A_S1_51 : 0|8@1+ (1,0) [0|255] ""  MBMU,PC
 SG_ BAT_U_HVS_51 : 8|16@1+ (0.1,0) [0|6553.5] "V"  MBMU,PC
 SG_ BAT_U_TOT_HVS_51 : 24|16@1+ (0.1,0) [0|6553.5] "V"  MBMU,PC
 SG_ HIS_NumofChg_DisChgCycles_51 : 40|16@1+ (1,0) [0|65535] ""  MBMU,PC
 SG_ BAT_standingstatus_51 : 56|8@1+ (1,0) [0|255] ""  MBMU,PC

BO_ 2332163956 S2A_SUMDATA1__52: 8 SBMU
 SG_ CRC_S2A_S1_52 : 0|8@1+ (1,0) [0|255] ""  MBMU,PC
 SG_ BAT_U_HVS_52 : 8|16@1+ (0.1,0) [0|6553.5] "V"  MBMU,PC
 SG_ BAT_U_TOT_HVS_52 : 24|16@1+ (0.1,0) [0|6553.5] "V"  MBMU,PC
 SG_ HIS_NumofChg_DisChgCycles_52 : 40|16@1+ (1,0) [0|65535] ""  MBMU,PC
 SG_ BAT_standingstatus_52 : 56|8@1+ (1,0) [0|255] ""  MBMU,PC

BO_ 2332163957 S2A_SUMDATA1__53: 8 SBMU
 SG_ CRC_S2A_S1_53 : 0|8@1+ (1,0) [0|255] ""  MBMU,PC
 SG_ BAT_U_HVS_53 : 8|16@1+ (0.1,0) [0|6553.5] "V"  MBMU,PC
 SG_ BAT_U_TOT_HVS_53 : 24|16@1+ (0.1,0) [0|6553.5] "V"  MBMU,PC
 SG_ HIS_NumofChg_DisChgCycles_53 : 40|16@1+ (1,0) [0|65535] ""  MBMU,PC
 SG_ BAT_standingstatus_53 : 56|8@1+ (1,0) [0|255] ""  MBMU,PC

BO_ 2332163958 S2A_SUMDATA1__54: 8 SBMU
 SG_ CRC_S2A_S1_54 : 0|8@1+ (1,0) [0|255] ""  MBMU,PC
 SG_ BAT_U_HVS_54 : 8|16@1+ (0.1,0) [0|6553.5] "V"  MBMU,PC
 SG_ BAT_U_TOT_HVS_54 : 24|16@1+ (0.1,0) [0|6553.5] "V"  MBMU,PC
 SG_ HIS_NumofChg_DisChgCycles_54 : 40|16@1+ (1,0) [0|65535] ""  MBMU,PC
 SG_ BAT_standingstatus_54 : 56|8@1+ (1,0) [0|255] ""  MBMU,PC

BO_ 2332163959 S2A_SUMDATA1__55: 8 SBMU
 SG_ CRC_S2A_S1_55 : 0|8@1+ (1,0) [0|255] ""  MBMU,PC
 SG_ BAT_U_HVS_55 : 8|16@1+ (0.1,0) [0|6553.5] "V"  MBMU,PC
 SG_ BAT_U_TOT_HVS_55 : 24|16@1+ (0.1,0) [0|6553.5] "V"  MBMU,PC
 SG_ HIS_NumofChg_DisChgCycles_55 : 40|16@1+ (1,0) [0|65535] ""  MBMU,PC
 SG_ BAT_standingstatus_55 : 56|8@1+ (1,0) [0|255] ""  MBMU,PC

BO_ 2332163960 S2A_SUMDATA1__56: 8 SBMU
 SG_ CRC_S2A_S1_56 : 0|8@1+ (1,0) [0|255] ""  MBMU,PC
 SG_ BAT_U_HVS_56 : 8|16@1+ (0.1,0) [0|6553.5] "V"  MBMU,PC
 SG_ BAT_U_TOT_HVS_56 : 24|16@1+ (0.1,0) [0|6553.5] "V"  MBMU,PC
 SG_ HIS_NumofChg_DisChgCycles_56 : 40|16@1+ (1,0) [0|65535] ""  MBMU,PC
 SG_ BAT_standingstatus_56 : 56|8@1+ (1,0) [0|255] ""  MBMU,PC

BO_ 2332163961 S2A_SUMDATA1__57: 8 SBMU
 SG_ CRC_S2A_S1_57 : 0|8@1+ (1,0) [0|255] ""  MBMU,PC
 SG_ BAT_U_HVS_57 : 8|16@1+ (0.1,0) [0|6553.5] "V"  MBMU,PC
 SG_ BAT_U_TOT_HVS_57 : 24|16@1+ (0.1,0) [0|6553.5] "V"  MBMU,PC
 SG_ HIS_NumofChg_DisChgCycles_57 : 40|16@1+ (1,0) [0|65535] ""  MBMU,PC
 SG_ BAT_standingstatus_57 : 56|8@1+ (1,0) [0|255] ""  MBMU,PC

BO_ 2332163962 S2A_SUMDATA1__58: 8 SBMU
 SG_ CRC_S2A_S1_58 : 0|8@1+ (1,0) [0|255] ""  MBMU,PC
 SG_ BAT_U_HVS_58 : 8|16@1+ (0.1,0) [0|6553.5] "V"  MBMU,PC
 SG_ BAT_U_TOT_HVS_58 : 24|16@1+ (0.1,0) [0|6553.5] "V"  MBMU,PC
 SG_ HIS_NumofChg_DisChgCycles_58 : 40|16@1+ (1,0) [0|65535] ""  MBMU,PC
 SG_ BAT_standingstatus_58 : 56|8@1+ (1,0) [0|255] ""  MBMU,PC

BO_ 2332163963 S2A_SUMDATA1__59: 8 SBMU
 SG_ CRC_S2A_S1_59 : 0|8@1+ (1,0) [0|255] ""  MBMU,PC
 SG_ BAT_U_HVS_59 : 8|16@1+ (0.1,0) [0|6553.5] "V"  MBMU,PC
 SG_ BAT_U_TOT_HVS_59 : 24|16@1+ (0.1,0) [0|6553.5] "V"  MBMU,PC
 SG_ HIS_NumofChg_DisChgCycles_59 : 40|16@1+ (1,0) [0|65535] ""  MBMU,PC
 SG_ BAT_standingstatus_59 : 56|8@1+ (1,0) [0|255] ""  MBMU,PC

BO_ 2332163964 S2A_SUMDATA1__60: 8 SBMU
 SG_ CRC_S2A_S1_60 : 0|8@1+ (1,0) [0|255] ""  MBMU,PC
 SG_ BAT_U_HVS_60 : 8|16@1+ (0.1,0) [0|6553.5] "V"  MBMU,PC
 SG_ BAT_U_TOT_HVS_60 : 24|16@1+ (0.1,0) [0|6553.5] "V"  MBMU,PC
 SG_ HIS_NumofChg_DisChgCycles_60 : 40|16@1+ (1,0) [0|65535] ""  MBMU,PC
 SG_ BAT_standingstatus_60 : 56|8@1+ (1,0) [0|255] ""  MBMU,PC

BO_ 2332163965 S2A_SUMDATA1__61: 8 SBMU
 SG_ CRC_S2A_S1_61 : 0|8@1+ (1,0) [0|255] ""  MBMU,PC
 SG_ BAT_U_HVS_61 : 8|16@1+ (0.1,0) [0|6553.5] "V"  MBMU,PC
 SG_ BAT_U_TOT_HVS_61 : 24|16@1+ (0.1,0) [0|6553.5] "V"  MBMU,PC
 SG_ HIS_NumofChg_DisChgCycles_61 : 40|16@1+ (1,0) [0|65535] ""  MBMU,PC
 SG_ BAT_standingstatus_61 : 56|8@1+ (1,0) [0|255] ""  MBMU,PC

BO_ 2332163966 S2A_SUMDATA1__62: 8 SBMU
 SG_ CRC_S2A_S1_62 : 0|8@1+ (1,0) [0|255] ""  MBMU,PC
 SG_ BAT_U_HVS_62 : 8|16@1+ (0.1,0) [0|6553.5] "V"  MBMU,PC
 SG_ BAT_U_TOT_HVS_62 : 24|16@1+ (0.1,0) [0|6553.5] "V"  MBMU,PC
 SG_ HIS_NumofChg_DisChgCycles_62 : 40|16@1+ (1,0) [0|65535] ""  MBMU,PC
 SG_ BAT_standingstatus_62 : 56|8@1+ (1,0) [0|255] ""  MBMU,PC

BO_ 2332163967 S2A_SUMDATA1__63: 8 SBMU
 SG_ CRC_S2A_S1_63 : 0|8@1+ (1,0) [0|255] ""  MBMU,PC
 SG_ BAT_U_HVS_63 : 8|16@1+ (0.1,0) [0|6553.5] "V"  MBMU,PC
 SG_ BAT_U_TOT_HVS_63 : 24|16@1+ (0.1,0) [0|6553.5] "V"  MBMU,PC
 SG_ HIS_NumofChg_DisChgCycles_63 : 40|16@1+ (1,0) [0|65535] ""  MBMU,PC
 SG_ BAT_standingstatus_63 : 56|8@1+ (1,0) [0|255] ""  MBMU,PC

BO_ 2332229441 S2A_SUMDATA2__01: 8 SBMU
 SG_ CRC_S2A_S2_01 : 0|8@1+ (1,0) [0|255] ""  MBMU,PC
 SG_ ALIV_ST_SW_HVS_01 : 8|4@1+ (1,0) [0|15] ""  MBMU,PC
 SG_ ST_PreCharge_SW_HVS_01 : 12|1@1+ (1,0) [0|1] ""  MBMU,PC
 SG_ ST_Main_POS_SW_HVS_01 : 13|1@1+ (1,0) [0|1] ""  MBMU,PC
 SG_ ST_Main_NEG_SW_HVS_01 : 14|1@1+ (1,0) [0|1] ""  MBMU,PC
 SG_ ST_System_01 : 17|1@1+ (1,0) [0|1] ""  MBMU,PC
 SG_ ST_CALIBRATION_01 : 18|1@1+ (1,0) [0|1] ""  MBMU,PC
 SG_ ST_Insulation_01 : 19|2@1+ (1,0) [0|3] ""  MBMU,PC
 SG_ ST_PowerDown_01 : 21|3@1+ (1,0) [0|7] ""  MBMU,PC
 SG_ ST_pwr12V_01 : 24|1@1+ (1,0) [0|1] ""  MBMU,PC
 SG_ ST_pwr5V_01 : 25|1@1+ (1,0) [0|1] ""  MBMU,PC
 SG_ ST_pwr24V_01 : 26|1@1+ (1,0) [0|1] ""  MBMU,PC
 SG_ ST_pwrStatus_01 : 27|3@1+ (1,0) [0|7] ""  MBMU,PC
 SG_ S2A_S2_FullChgFlgFromSBMU_01 : 30|8@1+ (1,0) [0|255] ""  MBMU,PC
 SG_ ST_cscStandby_01 : 46|2@1+ (1,0) [0|3] ""  MBMU,PC
 SG_ ST_OffReasonMsg_01 : 48|16@1+ (1,0) [0|65535] ""  MBMU,PC

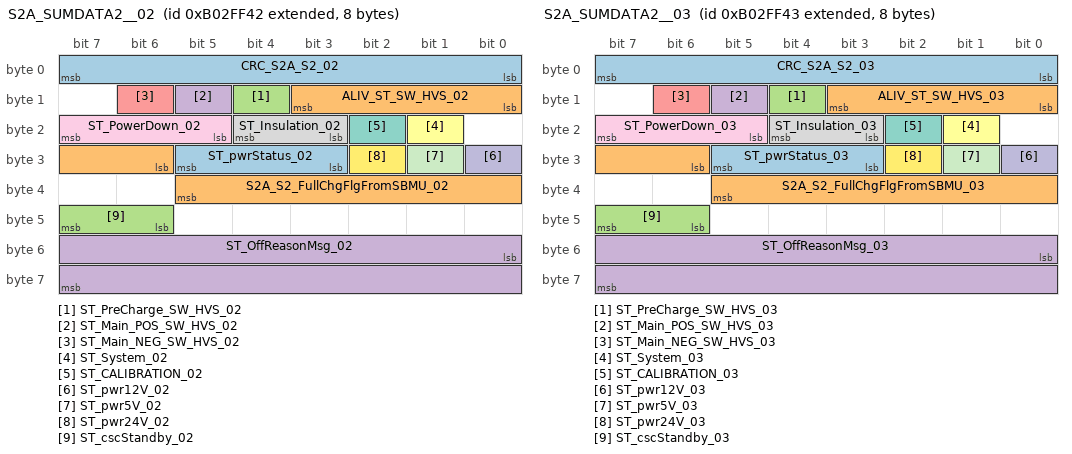
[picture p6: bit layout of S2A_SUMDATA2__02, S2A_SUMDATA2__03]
BO_ 2332229442 S2A_SUMDATA2__02: 8 SBMU
 SG_ CRC_S2A_S2_02 : 0|8@1+ (1,0) [0|255] ""  MBMU,PC
 SG_ ALIV_ST_SW_HVS_02 : 8|4@1+ (1,0) [0|15] ""  MBMU,PC
 SG_ ST_PreCharge_SW_HVS_02 : 12|1@1+ (1,0) [0|1] ""  MBMU,PC
 SG_ ST_Main_POS_SW_HVS_02 : 13|1@1+ (1,0) [0|1] ""  MBMU,PC
 SG_ ST_Main_NEG_SW_HVS_02 : 14|1@1+ (1,0) [0|1] ""  MBMU,PC
 SG_ ST_System_02 : 17|1@1+ (1,0) [0|1] ""  MBMU,PC
 SG_ ST_CALIBRATION_02 : 18|1@1+ (1,0) [0|1] ""  MBMU,PC
 SG_ ST_Insulation_02 : 19|2@1+ (1,0) [0|3] ""  MBMU,PC
 SG_ ST_PowerDown_02 : 21|3@1+ (1,0) [0|7] ""  MBMU,PC
 SG_ ST_pwr12V_02 : 24|1@1+ (1,0) [0|1] ""  MBMU,PC
 SG_ ST_pwr5V_02 : 25|1@1+ (1,0) [0|1] ""  MBMU,PC
 SG_ ST_pwr24V_02 : 26|1@1+ (1,0) [0|1] ""  MBMU,PC
 SG_ ST_pwrStatus_02 : 27|3@1+ (1,0) [0|7] ""  MBMU,PC
 SG_ S2A_S2_FullChgFlgFromSBMU_02 : 30|8@1+ (1,0) [0|255] ""  MBMU,PC
 SG_ ST_cscStandby_02 : 46|2@1+ (1,0) [0|3] ""  MBMU,PC
 SG_ ST_OffReasonMsg_02 : 48|16@1+ (1,0) [0|65535] ""  MBMU,PC

BO_ 2332229443 S2A_SUMDATA2__03: 8 SBMU
 SG_ CRC_S2A_S2_03 : 0|8@1+ (1,0) [0|255] ""  MBMU,PC
 SG_ ALIV_ST_SW_HVS_03 : 8|4@1+ (1,0) [0|15] ""  MBMU,PC
 SG_ ST_PreCharge_SW_HVS_03 : 12|1@1+ (1,0) [0|1] ""  MBMU,PC
 SG_ ST_Main_POS_SW_HVS_03 : 13|1@1+ (1,0) [0|1] ""  MBMU,PC
 SG_ ST_Main_NEG_SW_HVS_03 : 14|1@1+ (1,0) [0|1] ""  MBMU,PC
 SG_ ST_System_03 : 17|1@1+ (1,0) [0|1] ""  MBMU,PC
 SG_ ST_CALIBRATION_03 : 18|1@1+ (1,0) [0|1] ""  MBMU,PC
 SG_ ST_Insulation_03 : 19|2@1+ (1,0) [0|3] ""  MBMU,PC
 SG_ ST_PowerDown_03 : 21|3@1+ (1,0) [0|7] ""  MBMU,PC
 SG_ ST_pwr12V_03 : 24|1@1+ (1,0) [0|1] ""  MBMU,PC
 SG_ ST_pwr5V_03 : 25|1@1+ (1,0) [0|1] ""  MBMU,PC
 SG_ ST_pwr24V_03 : 26|1@1+ (1,0) [0|1] ""  MBMU,PC
 SG_ ST_pwrStatus_03 : 27|3@1+ (1,0) [0|7] ""  MBMU,PC
 SG_ S2A_S2_FullChgFlgFromSBMU_03 : 30|8@1+ (1,0) [0|255] ""  MBMU,PC
 SG_ ST_cscStandby_03 : 46|2@1+ (1,0) [0|3] ""  MBMU,PC
 SG_ ST_OffReasonMsg_03 : 48|16@1+ (1,0) [0|65535] ""  MBMU,PC

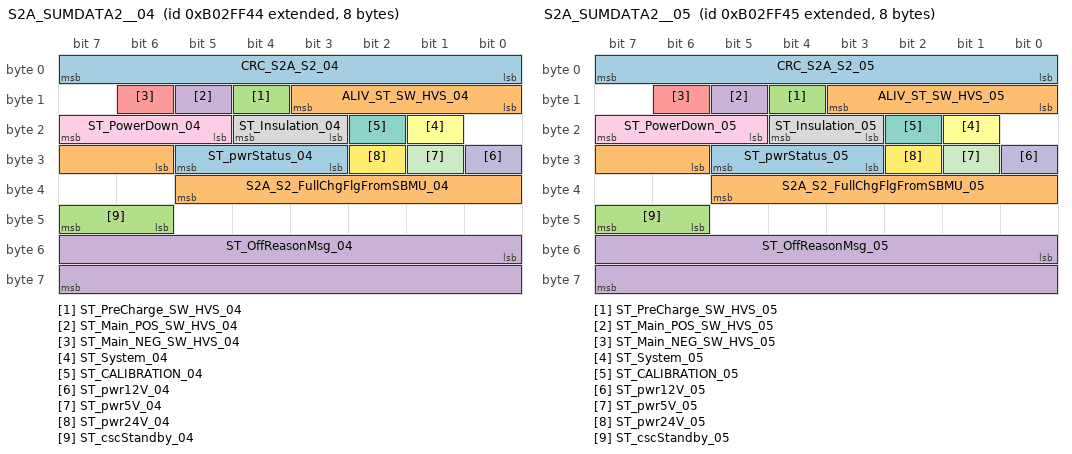
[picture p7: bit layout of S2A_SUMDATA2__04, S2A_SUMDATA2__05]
BO_ 2332229444 S2A_SUMDATA2__04: 8 SBMU
 SG_ CRC_S2A_S2_04 : 0|8@1+ (1,0) [0|255] ""  MBMU,PC
 SG_ ALIV_ST_SW_HVS_04 : 8|4@1+ (1,0) [0|15] ""  MBMU,PC
 SG_ ST_PreCharge_SW_HVS_04 : 12|1@1+ (1,0) [0|1] ""  MBMU,PC
 SG_ ST_Main_POS_SW_HVS_04 : 13|1@1+ (1,0) [0|1] ""  MBMU,PC
 SG_ ST_Main_NEG_SW_HVS_04 : 14|1@1+ (1,0) [0|1] ""  MBMU,PC
 SG_ ST_System_04 : 17|1@1+ (1,0) [0|1] ""  MBMU,PC
 SG_ ST_CALIBRATION_04 : 18|1@1+ (1,0) [0|1] ""  MBMU,PC
 SG_ ST_Insulation_04 : 19|2@1+ (1,0) [0|3] ""  MBMU,PC
 SG_ ST_PowerDown_04 : 21|3@1+ (1,0) [0|7] ""  MBMU,PC
 SG_ ST_pwr12V_04 : 24|1@1+ (1,0) [0|1] ""  MBMU,PC
 SG_ ST_pwr5V_04 : 25|1@1+ (1,0) [0|1] ""  MBMU,PC
 SG_ ST_pwr24V_04 : 26|1@1+ (1,0) [0|1] ""  MBMU,PC
 SG_ ST_pwrStatus_04 : 27|3@1+ (1,0) [0|7] ""  MBMU,PC
 SG_ S2A_S2_FullChgFlgFromSBMU_04 : 30|8@1+ (1,0) [0|255] ""  MBMU,PC
 SG_ ST_cscStandby_04 : 46|2@1+ (1,0) [0|3] ""  MBMU,PC
 SG_ ST_OffReasonMsg_04 : 48|16@1+ (1,0) [0|65535] ""  MBMU,PC

BO_ 2332229445 S2A_SUMDATA2__05: 8 SBMU
 SG_ CRC_S2A_S2_05 : 0|8@1+ (1,0) [0|255] ""  MBMU,PC
 SG_ ALIV_ST_SW_HVS_05 : 8|4@1+ (1,0) [0|15] ""  MBMU,PC
 SG_ ST_PreCharge_SW_HVS_05 : 12|1@1+ (1,0) [0|1] ""  MBMU,PC
 SG_ ST_Main_POS_SW_HVS_05 : 13|1@1+ (1,0) [0|1] ""  MBMU,PC
 SG_ ST_Main_NEG_SW_HVS_05 : 14|1@1+ (1,0) [0|1] ""  MBMU,PC
 SG_ ST_System_05 : 17|1@1+ (1,0) [0|1] ""  MBMU,PC
 SG_ ST_CALIBRATION_05 : 18|1@1+ (1,0) [0|1] ""  MBMU,PC
 SG_ ST_Insulation_05 : 19|2@1+ (1,0) [0|3] ""  MBMU,PC
 SG_ ST_PowerDown_05 : 21|3@1+ (1,0) [0|7] ""  MBMU,PC
 SG_ ST_pwr12V_05 : 24|1@1+ (1,0) [0|1] ""  MBMU,PC
 SG_ ST_pwr5V_05 : 25|1@1+ (1,0) [0|1] ""  MBMU,PC
 SG_ ST_pwr24V_05 : 26|1@1+ (1,0) [0|1] ""  MBMU,PC
 SG_ ST_pwrStatus_05 : 27|3@1+ (1,0) [0|7] ""  MBMU,PC
 SG_ S2A_S2_FullChgFlgFromSBMU_05 : 30|8@1+ (1,0) [0|255] ""  MBMU,PC
 SG_ ST_cscStandby_05 : 46|2@1+ (1,0) [0|3] ""  MBMU,PC
 SG_ ST_OffReasonMsg_05 : 48|16@1+ (1,0) [0|65535] ""  MBMU,PC

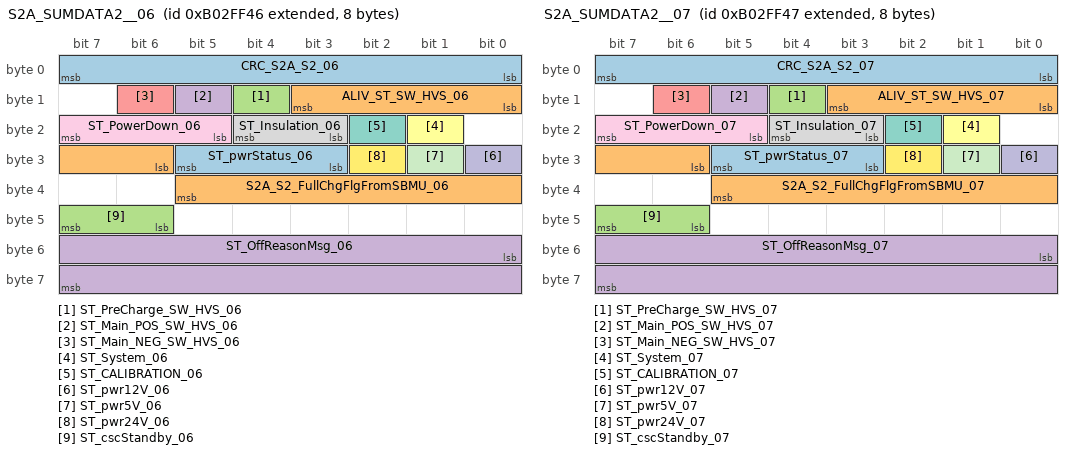
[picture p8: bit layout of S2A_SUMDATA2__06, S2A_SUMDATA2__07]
BO_ 2332229446 S2A_SUMDATA2__06: 8 SBMU
 SG_ CRC_S2A_S2_06 : 0|8@1+ (1,0) [0|255] ""  MBMU,PC
 SG_ ALIV_ST_SW_HVS_06 : 8|4@1+ (1,0) [0|15] ""  MBMU,PC
 SG_ ST_PreCharge_SW_HVS_06 : 12|1@1+ (1,0) [0|1] ""  MBMU,PC
 SG_ ST_Main_POS_SW_HVS_06 : 13|1@1+ (1,0) [0|1] ""  MBMU,PC
 SG_ ST_Main_NEG_SW_HVS_06 : 14|1@1+ (1,0) [0|1] ""  MBMU,PC
 SG_ ST_System_06 : 17|1@1+ (1,0) [0|1] ""  MBMU,PC
 SG_ ST_CALIBRATION_06 : 18|1@1+ (1,0) [0|1] ""  MBMU,PC
 SG_ ST_Insulation_06 : 19|2@1+ (1,0) [0|3] ""  MBMU,PC
 SG_ ST_PowerDown_06 : 21|3@1+ (1,0) [0|7] ""  MBMU,PC
 SG_ ST_pwr12V_06 : 24|1@1+ (1,0) [0|1] ""  MBMU,PC
 SG_ ST_pwr5V_06 : 25|1@1+ (1,0) [0|1] ""  MBMU,PC
 SG_ ST_pwr24V_06 : 26|1@1+ (1,0) [0|1] ""  MBMU,PC
 SG_ ST_pwrStatus_06 : 27|3@1+ (1,0) [0|7] ""  MBMU,PC
 SG_ S2A_S2_FullChgFlgFromSBMU_06 : 30|8@1+ (1,0) [0|255] ""  MBMU,PC
 SG_ ST_cscStandby_06 : 46|2@1+ (1,0) [0|3] ""  MBMU,PC
 SG_ ST_OffReasonMsg_06 : 48|16@1+ (1,0) [0|65535] ""  MBMU,PC

BO_ 2332229447 S2A_SUMDATA2__07: 8 SBMU
 SG_ CRC_S2A_S2_07 : 0|8@1+ (1,0) [0|255] ""  MBMU,PC
 SG_ ALIV_ST_SW_HVS_07 : 8|4@1+ (1,0) [0|15] ""  MBMU,PC
 SG_ ST_PreCharge_SW_HVS_07 : 12|1@1+ (1,0) [0|1] ""  MBMU,PC
 SG_ ST_Main_POS_SW_HVS_07 : 13|1@1+ (1,0) [0|1] ""  MBMU,PC
 SG_ ST_Main_NEG_SW_HVS_07 : 14|1@1+ (1,0) [0|1] ""  MBMU,PC
 SG_ ST_System_07 : 17|1@1+ (1,0) [0|1] ""  MBMU,PC
 SG_ ST_CALIBRATION_07 : 18|1@1+ (1,0) [0|1] ""  MBMU,PC
 SG_ ST_Insulation_07 : 19|2@1+ (1,0) [0|3] ""  MBMU,PC
 SG_ ST_PowerDown_07 : 21|3@1+ (1,0) [0|7] ""  MBMU,PC
 SG_ ST_pwr12V_07 : 24|1@1+ (1,0) [0|1] ""  MBMU,PC
 SG_ ST_pwr5V_07 : 25|1@1+ (1,0) [0|1] ""  MBMU,PC
 SG_ ST_pwr24V_07 : 26|1@1+ (1,0) [0|1] ""  MBMU,PC
 SG_ ST_pwrStatus_07 : 27|3@1+ (1,0) [0|7] ""  MBMU,PC
 SG_ S2A_S2_FullChgFlgFromSBMU_07 : 30|8@1+ (1,0) [0|255] ""  MBMU,PC
 SG_ ST_cscStandby_07 : 46|2@1+ (1,0) [0|3] ""  MBMU,PC
 SG_ ST_OffReasonMsg_07 : 48|16@1+ (1,0) [0|65535] ""  MBMU,PC

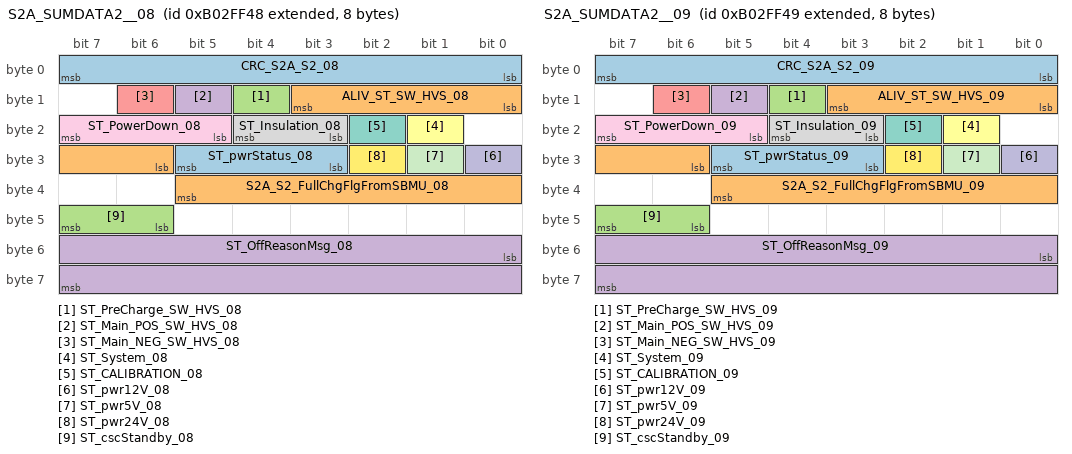
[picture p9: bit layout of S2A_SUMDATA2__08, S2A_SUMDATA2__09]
BO_ 2332229448 S2A_SUMDATA2__08: 8 SBMU
 SG_ CRC_S2A_S2_08 : 0|8@1+ (1,0) [0|255] ""  MBMU,PC
 SG_ ALIV_ST_SW_HVS_08 : 8|4@1+ (1,0) [0|15] ""  MBMU,PC
 SG_ ST_PreCharge_SW_HVS_08 : 12|1@1+ (1,0) [0|1] ""  MBMU,PC
 SG_ ST_Main_POS_SW_HVS_08 : 13|1@1+ (1,0) [0|1] ""  MBMU,PC
 SG_ ST_Main_NEG_SW_HVS_08 : 14|1@1+ (1,0) [0|1] ""  MBMU,PC
 SG_ ST_System_08 : 17|1@1+ (1,0) [0|1] ""  MBMU,PC
 SG_ ST_CALIBRATION_08 : 18|1@1+ (1,0) [0|1] ""  MBMU,PC
 SG_ ST_Insulation_08 : 19|2@1+ (1,0) [0|3] ""  MBMU,PC
 SG_ ST_PowerDown_08 : 21|3@1+ (1,0) [0|7] ""  MBMU,PC
 SG_ ST_pwr12V_08 : 24|1@1+ (1,0) [0|1] ""  MBMU,PC
 SG_ ST_pwr5V_08 : 25|1@1+ (1,0) [0|1] ""  MBMU,PC
 SG_ ST_pwr24V_08 : 26|1@1+ (1,0) [0|1] ""  MBMU,PC
 SG_ ST_pwrStatus_08 : 27|3@1+ (1,0) [0|7] ""  MBMU,PC
 SG_ S2A_S2_FullChgFlgFromSBMU_08 : 30|8@1+ (1,0) [0|255] ""  MBMU,PC
 SG_ ST_cscStandby_08 : 46|2@1+ (1,0) [0|3] ""  MBMU,PC
 SG_ ST_OffReasonMsg_08 : 48|16@1+ (1,0) [0|65535] ""  MBMU,PC

BO_ 2332229449 S2A_SUMDATA2__09: 8 SBMU
 SG_ CRC_S2A_S2_09 : 0|8@1+ (1,0) [0|255] ""  MBMU,PC
 SG_ ALIV_ST_SW_HVS_09 : 8|4@1+ (1,0) [0|15] ""  MBMU,PC
 SG_ ST_PreCharge_SW_HVS_09 : 12|1@1+ (1,0) [0|1] ""  MBMU,PC
 SG_ ST_Main_POS_SW_HVS_09 : 13|1@1+ (1,0) [0|1] ""  MBMU,PC
 SG_ ST_Main_NEG_SW_HVS_09 : 14|1@1+ (1,0) [0|1] ""  MBMU,PC
 SG_ ST_System_09 : 17|1@1+ (1,0) [0|1] ""  MBMU,PC
 SG_ ST_CALIBRATION_09 : 18|1@1+ (1,0) [0|1] ""  MBMU,PC
 SG_ ST_Insulation_09 : 19|2@1+ (1,0) [0|3] ""  MBMU,PC
 SG_ ST_PowerDown_09 : 21|3@1+ (1,0) [0|7] ""  MBMU,PC
 SG_ ST_pwr12V_09 : 24|1@1+ (1,0) [0|1] ""  MBMU,PC
 SG_ ST_pwr5V_09 : 25|1@1+ (1,0) [0|1] ""  MBMU,PC
 SG_ ST_pwr24V_09 : 26|1@1+ (1,0) [0|1] ""  MBMU,PC
 SG_ ST_pwrStatus_09 : 27|3@1+ (1,0) [0|7] ""  MBMU,PC
 SG_ S2A_S2_FullChgFlgFromSBMU_09 : 30|8@1+ (1,0) [0|255] ""  MBMU,PC
 SG_ ST_cscStandby_09 : 46|2@1+ (1,0) [0|3] ""  MBMU,PC
 SG_ ST_OffReasonMsg_09 : 48|16@1+ (1,0) [0|65535] ""  MBMU,PC

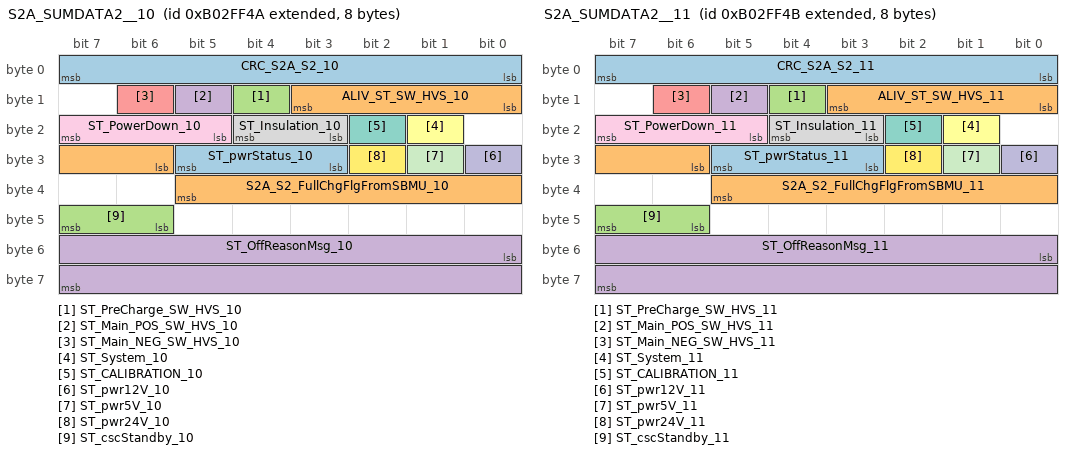
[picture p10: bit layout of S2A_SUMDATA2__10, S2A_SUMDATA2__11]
BO_ 2332229450 S2A_SUMDATA2__10: 8 SBMU
 SG_ CRC_S2A_S2_10 : 0|8@1+ (1,0) [0|255] ""  MBMU,PC
 SG_ ALIV_ST_SW_HVS_10 : 8|4@1+ (1,0) [0|15] ""  MBMU,PC
 SG_ ST_PreCharge_SW_HVS_10 : 12|1@1+ (1,0) [0|1] ""  MBMU,PC
 SG_ ST_Main_POS_SW_HVS_10 : 13|1@1+ (1,0) [0|1] ""  MBMU,PC
 SG_ ST_Main_NEG_SW_HVS_10 : 14|1@1+ (1,0) [0|1] ""  MBMU,PC
 SG_ ST_System_10 : 17|1@1+ (1,0) [0|1] ""  MBMU,PC
 SG_ ST_CALIBRATION_10 : 18|1@1+ (1,0) [0|1] ""  MBMU,PC
 SG_ ST_Insulation_10 : 19|2@1+ (1,0) [0|3] ""  MBMU,PC
 SG_ ST_PowerDown_10 : 21|3@1+ (1,0) [0|7] ""  MBMU,PC
 SG_ ST_pwr12V_10 : 24|1@1+ (1,0) [0|1] ""  MBMU,PC
 SG_ ST_pwr5V_10 : 25|1@1+ (1,0) [0|1] ""  MBMU,PC
 SG_ ST_pwr24V_10 : 26|1@1+ (1,0) [0|1] ""  MBMU,PC
 SG_ ST_pwrStatus_10 : 27|3@1+ (1,0) [0|7] ""  MBMU,PC
 SG_ S2A_S2_FullChgFlgFromSBMU_10 : 30|8@1+ (1,0) [0|255] ""  MBMU,PC
 SG_ ST_cscStandby_10 : 46|2@1+ (1,0) [0|3] ""  MBMU,PC
 SG_ ST_OffReasonMsg_10 : 48|16@1+ (1,0) [0|65535] ""  MBMU,PC

BO_ 2332229451 S2A_SUMDATA2__11: 8 SBMU
 SG_ CRC_S2A_S2_11 : 0|8@1+ (1,0) [0|255] ""  MBMU,PC
 SG_ ALIV_ST_SW_HVS_11 : 8|4@1+ (1,0) [0|15] ""  MBMU,PC
 SG_ ST_PreCharge_SW_HVS_11 : 12|1@1+ (1,0) [0|1] ""  MBMU,PC
 SG_ ST_Main_POS_SW_HVS_11 : 13|1@1+ (1,0) [0|1] ""  MBMU,PC
 SG_ ST_Main_NEG_SW_HVS_11 : 14|1@1+ (1,0) [0|1] ""  MBMU,PC
 SG_ ST_System_11 : 17|1@1+ (1,0) [0|1] ""  MBMU,PC
 SG_ ST_CALIBRATION_11 : 18|1@1+ (1,0) [0|1] ""  MBMU,PC
 SG_ ST_Insulation_11 : 19|2@1+ (1,0) [0|3] ""  MBMU,PC
 SG_ ST_PowerDown_11 : 21|3@1+ (1,0) [0|7] ""  MBMU,PC
 SG_ ST_pwr12V_11 : 24|1@1+ (1,0) [0|1] ""  MBMU,PC
 SG_ ST_pwr5V_11 : 25|1@1+ (1,0) [0|1] ""  MBMU,PC
 SG_ ST_pwr24V_11 : 26|1@1+ (1,0) [0|1] ""  MBMU,PC
 SG_ ST_pwrStatus_11 : 27|3@1+ (1,0) [0|7] ""  MBMU,PC
 SG_ S2A_S2_FullChgFlgFromSBMU_11 : 30|8@1+ (1,0) [0|255] ""  MBMU,PC
 SG_ ST_cscStandby_11 : 46|2@1+ (1,0) [0|3] ""  MBMU,PC
 SG_ ST_OffReasonMsg_11 : 48|16@1+ (1,0) [0|65535] ""  MBMU,PC

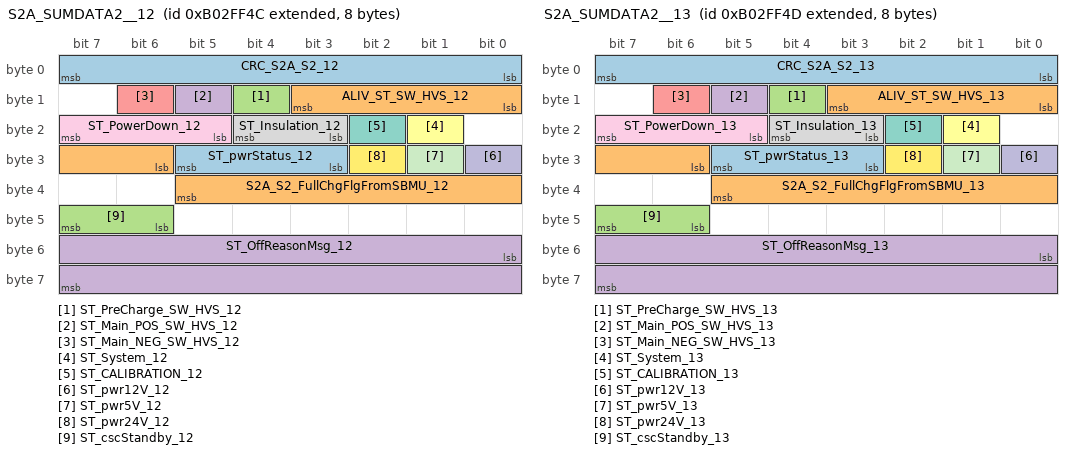
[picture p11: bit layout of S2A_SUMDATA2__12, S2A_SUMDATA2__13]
BO_ 2332229452 S2A_SUMDATA2__12: 8 SBMU
 SG_ CRC_S2A_S2_12 : 0|8@1+ (1,0) [0|255] ""  MBMU,PC
 SG_ ALIV_ST_SW_HVS_12 : 8|4@1+ (1,0) [0|15] ""  MBMU,PC
 SG_ ST_PreCharge_SW_HVS_12 : 12|1@1+ (1,0) [0|1] ""  MBMU,PC
 SG_ ST_Main_POS_SW_HVS_12 : 13|1@1+ (1,0) [0|1] ""  MBMU,PC
 SG_ ST_Main_NEG_SW_HVS_12 : 14|1@1+ (1,0) [0|1] ""  MBMU,PC
 SG_ ST_System_12 : 17|1@1+ (1,0) [0|1] ""  MBMU,PC
 SG_ ST_CALIBRATION_12 : 18|1@1+ (1,0) [0|1] ""  MBMU,PC
 SG_ ST_Insulation_12 : 19|2@1+ (1,0) [0|3] ""  MBMU,PC
 SG_ ST_PowerDown_12 : 21|3@1+ (1,0) [0|7] ""  MBMU,PC
 SG_ ST_pwr12V_12 : 24|1@1+ (1,0) [0|1] ""  MBMU,PC
 SG_ ST_pwr5V_12 : 25|1@1+ (1,0) [0|1] ""  MBMU,PC
 SG_ ST_pwr24V_12 : 26|1@1+ (1,0) [0|1] ""  MBMU,PC
 SG_ ST_pwrStatus_12 : 27|3@1+ (1,0) [0|7] ""  MBMU,PC
 SG_ S2A_S2_FullChgFlgFromSBMU_12 : 30|8@1+ (1,0) [0|255] ""  MBMU,PC
 SG_ ST_cscStandby_12 : 46|2@1+ (1,0) [0|3] ""  MBMU,PC
 SG_ ST_OffReasonMsg_12 : 48|16@1+ (1,0) [0|65535] ""  MBMU,PC

BO_ 2332229453 S2A_SUMDATA2__13: 8 SBMU
 SG_ CRC_S2A_S2_13 : 0|8@1+ (1,0) [0|255] ""  MBMU,PC
 SG_ ALIV_ST_SW_HVS_13 : 8|4@1+ (1,0) [0|15] ""  MBMU,PC
 SG_ ST_PreCharge_SW_HVS_13 : 12|1@1+ (1,0) [0|1] ""  MBMU,PC
 SG_ ST_Main_POS_SW_HVS_13 : 13|1@1+ (1,0) [0|1] ""  MBMU,PC
 SG_ ST_Main_NEG_SW_HVS_13 : 14|1@1+ (1,0) [0|1] ""  MBMU,PC
 SG_ ST_System_13 : 17|1@1+ (1,0) [0|1] ""  MBMU,PC
 SG_ ST_CALIBRATION_13 : 18|1@1+ (1,0) [0|1] ""  MBMU,PC
 SG_ ST_Insulation_13 : 19|2@1+ (1,0) [0|3] ""  MBMU,PC
 SG_ ST_PowerDown_13 : 21|3@1+ (1,0) [0|7] ""  MBMU,PC
 SG_ ST_pwr12V_13 : 24|1@1+ (1,0) [0|1] ""  MBMU,PC
 SG_ ST_pwr5V_13 : 25|1@1+ (1,0) [0|1] ""  MBMU,PC
 SG_ ST_pwr24V_13 : 26|1@1+ (1,0) [0|1] ""  MBMU,PC
 SG_ ST_pwrStatus_13 : 27|3@1+ (1,0) [0|7] ""  MBMU,PC
 SG_ S2A_S2_FullChgFlgFromSBMU_13 : 30|8@1+ (1,0) [0|255] ""  MBMU,PC
 SG_ ST_cscStandby_13 : 46|2@1+ (1,0) [0|3] ""  MBMU,PC
 SG_ ST_OffReasonMsg_13 : 48|16@1+ (1,0) [0|65535] ""  MBMU,PC

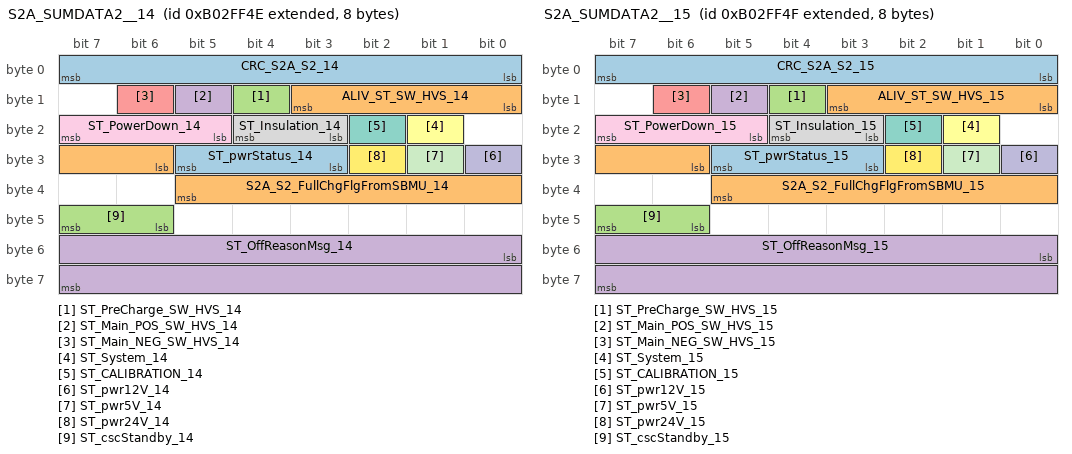
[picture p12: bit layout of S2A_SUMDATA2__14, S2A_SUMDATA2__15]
BO_ 2332229454 S2A_SUMDATA2__14: 8 SBMU
 SG_ CRC_S2A_S2_14 : 0|8@1+ (1,0) [0|255] ""  MBMU,PC
 SG_ ALIV_ST_SW_HVS_14 : 8|4@1+ (1,0) [0|15] ""  MBMU,PC
 SG_ ST_PreCharge_SW_HVS_14 : 12|1@1+ (1,0) [0|1] ""  MBMU,PC
 SG_ ST_Main_POS_SW_HVS_14 : 13|1@1+ (1,0) [0|1] ""  MBMU,PC
 SG_ ST_Main_NEG_SW_HVS_14 : 14|1@1+ (1,0) [0|1] ""  MBMU,PC
 SG_ ST_System_14 : 17|1@1+ (1,0) [0|1] ""  MBMU,PC
 SG_ ST_CALIBRATION_14 : 18|1@1+ (1,0) [0|1] ""  MBMU,PC
 SG_ ST_Insulation_14 : 19|2@1+ (1,0) [0|3] ""  MBMU,PC
 SG_ ST_PowerDown_14 : 21|3@1+ (1,0) [0|7] ""  MBMU,PC
 SG_ ST_pwr12V_14 : 24|1@1+ (1,0) [0|1] ""  MBMU,PC
 SG_ ST_pwr5V_14 : 25|1@1+ (1,0) [0|1] ""  MBMU,PC
 SG_ ST_pwr24V_14 : 26|1@1+ (1,0) [0|1] ""  MBMU,PC
 SG_ ST_pwrStatus_14 : 27|3@1+ (1,0) [0|7] ""  MBMU,PC
 SG_ S2A_S2_FullChgFlgFromSBMU_14 : 30|8@1+ (1,0) [0|255] ""  MBMU,PC
 SG_ ST_cscStandby_14 : 46|2@1+ (1,0) [0|3] ""  MBMU,PC
 SG_ ST_OffReasonMsg_14 : 48|16@1+ (1,0) [0|65535] ""  MBMU,PC

BO_ 2332229455 S2A_SUMDATA2__15: 8 SBMU
 SG_ CRC_S2A_S2_15 : 0|8@1+ (1,0) [0|255] ""  MBMU,PC
 SG_ ALIV_ST_SW_HVS_15 : 8|4@1+ (1,0) [0|15] ""  MBMU,PC
 SG_ ST_PreCharge_SW_HVS_15 : 12|1@1+ (1,0) [0|1] ""  MBMU,PC
 SG_ ST_Main_POS_SW_HVS_15 : 13|1@1+ (1,0) [0|1] ""  MBMU,PC
 SG_ ST_Main_NEG_SW_HVS_15 : 14|1@1+ (1,0) [0|1] ""  MBMU,PC
 SG_ ST_System_15 : 17|1@1+ (1,0) [0|1] ""  MBMU,PC
 SG_ ST_CALIBRATION_15 : 18|1@1+ (1,0) [0|1] ""  MBMU,PC
 SG_ ST_Insulation_15 : 19|2@1+ (1,0) [0|3] ""  MBMU,PC
 SG_ ST_PowerDown_15 : 21|3@1+ (1,0) [0|7] ""  MBMU,PC
 SG_ ST_pwr12V_15 : 24|1@1+ (1,0) [0|1] ""  MBMU,PC
 SG_ ST_pwr5V_15 : 25|1@1+ (1,0) [0|1] ""  MBMU,PC
 SG_ ST_pwr24V_15 : 26|1@1+ (1,0) [0|1] ""  MBMU,PC
 SG_ ST_pwrStatus_15 : 27|3@1+ (1,0) [0|7] ""  MBMU,PC
 SG_ S2A_S2_FullChgFlgFromSBMU_15 : 30|8@1+ (1,0) [0|255] ""  MBMU,PC
 SG_ ST_cscStandby_15 : 46|2@1+ (1,0) [0|3] ""  MBMU,PC
 SG_ ST_OffReasonMsg_15 : 48|16@1+ (1,0) [0|65535] ""  MBMU,PC

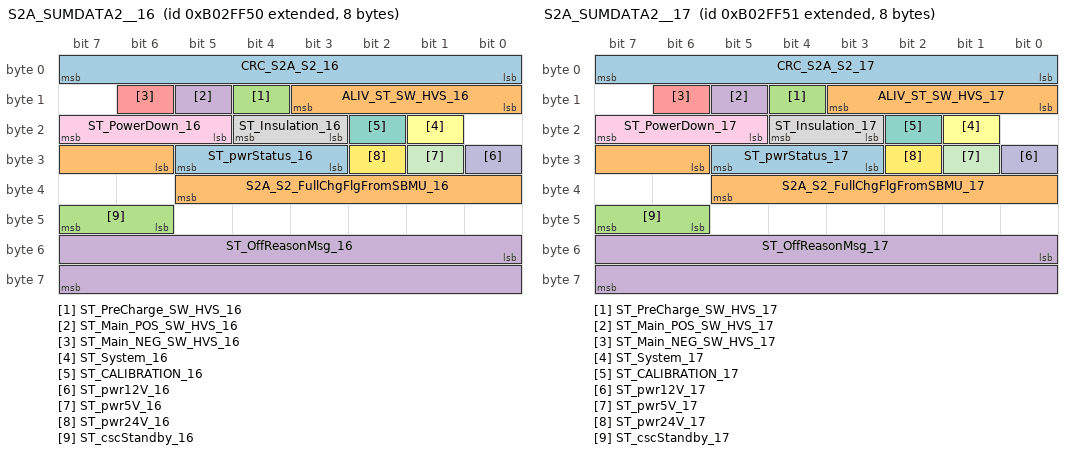
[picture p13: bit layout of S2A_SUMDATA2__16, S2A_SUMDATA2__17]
BO_ 2332229456 S2A_SUMDATA2__16: 8 SBMU
 SG_ CRC_S2A_S2_16 : 0|8@1+ (1,0) [0|255] ""  MBMU,PC
 SG_ ALIV_ST_SW_HVS_16 : 8|4@1+ (1,0) [0|15] ""  MBMU,PC
 SG_ ST_PreCharge_SW_HVS_16 : 12|1@1+ (1,0) [0|1] ""  MBMU,PC
 SG_ ST_Main_POS_SW_HVS_16 : 13|1@1+ (1,0) [0|1] ""  MBMU,PC
 SG_ ST_Main_NEG_SW_HVS_16 : 14|1@1+ (1,0) [0|1] ""  MBMU,PC
 SG_ ST_System_16 : 17|1@1+ (1,0) [0|1] ""  MBMU,PC
 SG_ ST_CALIBRATION_16 : 18|1@1+ (1,0) [0|1] ""  MBMU,PC
 SG_ ST_Insulation_16 : 19|2@1+ (1,0) [0|3] ""  MBMU,PC
 SG_ ST_PowerDown_16 : 21|3@1+ (1,0) [0|7] ""  MBMU,PC
 SG_ ST_pwr12V_16 : 24|1@1+ (1,0) [0|1] ""  MBMU,PC
 SG_ ST_pwr5V_16 : 25|1@1+ (1,0) [0|1] ""  MBMU,PC
 SG_ ST_pwr24V_16 : 26|1@1+ (1,0) [0|1] ""  MBMU,PC
 SG_ ST_pwrStatus_16 : 27|3@1+ (1,0) [0|7] ""  MBMU,PC
 SG_ S2A_S2_FullChgFlgFromSBMU_16 : 30|8@1+ (1,0) [0|255] ""  MBMU,PC
 SG_ ST_cscStandby_16 : 46|2@1+ (1,0) [0|3] ""  MBMU,PC
 SG_ ST_OffReasonMsg_16 : 48|16@1+ (1,0) [0|65535] ""  MBMU,PC

BO_ 2332229457 S2A_SUMDATA2__17: 8 SBMU
 SG_ CRC_S2A_S2_17 : 0|8@1+ (1,0) [0|255] ""  MBMU,PC
 SG_ ALIV_ST_SW_HVS_17 : 8|4@1+ (1,0) [0|15] ""  MBMU,PC
 SG_ ST_PreCharge_SW_HVS_17 : 12|1@1+ (1,0) [0|1] ""  MBMU,PC
 SG_ ST_Main_POS_SW_HVS_17 : 13|1@1+ (1,0) [0|1] ""  MBMU,PC
 SG_ ST_Main_NEG_SW_HVS_17 : 14|1@1+ (1,0) [0|1] ""  MBMU,PC
 SG_ ST_System_17 : 17|1@1+ (1,0) [0|1] ""  MBMU,PC
 SG_ ST_CALIBRATION_17 : 18|1@1+ (1,0) [0|1] ""  MBMU,PC
 SG_ ST_Insulation_17 : 19|2@1+ (1,0) [0|3] ""  MBMU,PC
 SG_ ST_PowerDown_17 : 21|3@1+ (1,0) [0|7] ""  MBMU,PC
 SG_ ST_pwr12V_17 : 24|1@1+ (1,0) [0|1] ""  MBMU,PC
 SG_ ST_pwr5V_17 : 25|1@1+ (1,0) [0|1] ""  MBMU,PC
 SG_ ST_pwr24V_17 : 26|1@1+ (1,0) [0|1] ""  MBMU,PC
 SG_ ST_pwrStatus_17 : 27|3@1+ (1,0) [0|7] ""  MBMU,PC
 SG_ S2A_S2_FullChgFlgFromSBMU_17 : 30|8@1+ (1,0) [0|255] ""  MBMU,PC
 SG_ ST_cscStandby_17 : 46|2@1+ (1,0) [0|3] ""  MBMU,PC
 SG_ ST_OffReasonMsg_17 : 48|16@1+ (1,0) [0|65535] ""  MBMU,PC

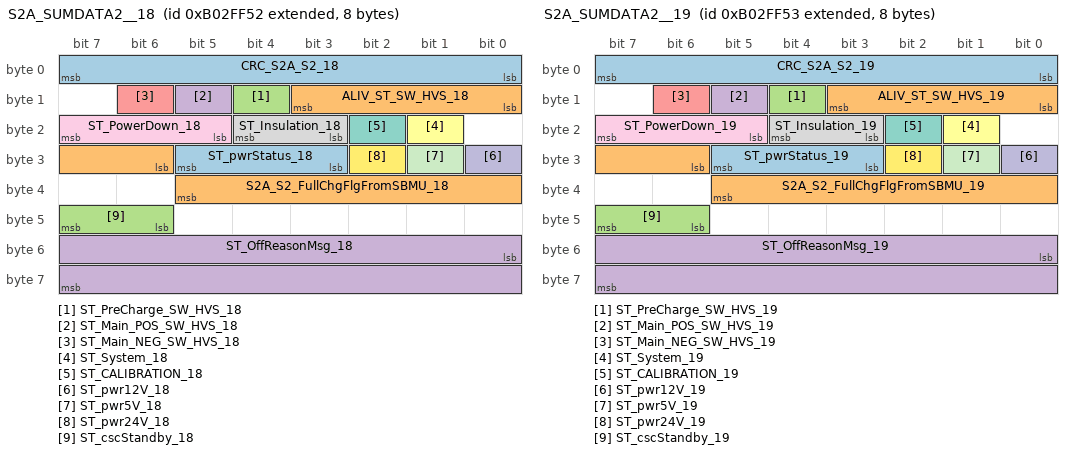
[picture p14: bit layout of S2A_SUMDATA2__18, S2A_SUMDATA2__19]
BO_ 2332229458 S2A_SUMDATA2__18: 8 SBMU
 SG_ CRC_S2A_S2_18 : 0|8@1+ (1,0) [0|255] ""  MBMU,PC
 SG_ ALIV_ST_SW_HVS_18 : 8|4@1+ (1,0) [0|15] ""  MBMU,PC
 SG_ ST_PreCharge_SW_HVS_18 : 12|1@1+ (1,0) [0|1] ""  MBMU,PC
 SG_ ST_Main_POS_SW_HVS_18 : 13|1@1+ (1,0) [0|1] ""  MBMU,PC
 SG_ ST_Main_NEG_SW_HVS_18 : 14|1@1+ (1,0) [0|1] ""  MBMU,PC
 SG_ ST_System_18 : 17|1@1+ (1,0) [0|1] ""  MBMU,PC
 SG_ ST_CALIBRATION_18 : 18|1@1+ (1,0) [0|1] ""  MBMU,PC
 SG_ ST_Insulation_18 : 19|2@1+ (1,0) [0|3] ""  MBMU,PC
 SG_ ST_PowerDown_18 : 21|3@1+ (1,0) [0|7] ""  MBMU,PC
 SG_ ST_pwr12V_18 : 24|1@1+ (1,0) [0|1] ""  MBMU,PC
 SG_ ST_pwr5V_18 : 25|1@1+ (1,0) [0|1] ""  MBMU,PC
 SG_ ST_pwr24V_18 : 26|1@1+ (1,0) [0|1] ""  MBMU,PC
 SG_ ST_pwrStatus_18 : 27|3@1+ (1,0) [0|7] ""  MBMU,PC
 SG_ S2A_S2_FullChgFlgFromSBMU_18 : 30|8@1+ (1,0) [0|255] ""  MBMU,PC
 SG_ ST_cscStandby_18 : 46|2@1+ (1,0) [0|3] ""  MBMU,PC
 SG_ ST_OffReasonMsg_18 : 48|16@1+ (1,0) [0|65535] ""  MBMU,PC

BO_ 2332229459 S2A_SUMDATA2__19: 8 SBMU
 SG_ CRC_S2A_S2_19 : 0|8@1+ (1,0) [0|255] ""  MBMU,PC
 SG_ ALIV_ST_SW_HVS_19 : 8|4@1+ (1,0) [0|15] ""  MBMU,PC
 SG_ ST_PreCharge_SW_HVS_19 : 12|1@1+ (1,0) [0|1] ""  MBMU,PC
 SG_ ST_Main_POS_SW_HVS_19 : 13|1@1+ (1,0) [0|1] ""  MBMU,PC
 SG_ ST_Main_NEG_SW_HVS_19 : 14|1@1+ (1,0) [0|1] ""  MBMU,PC
 SG_ ST_System_19 : 17|1@1+ (1,0) [0|1] ""  MBMU,PC
 SG_ ST_CALIBRATION_19 : 18|1@1+ (1,0) [0|1] ""  MBMU,PC
 SG_ ST_Insulation_19 : 19|2@1+ (1,0) [0|3] ""  MBMU,PC
 SG_ ST_PowerDown_19 : 21|3@1+ (1,0) [0|7] ""  MBMU,PC
 SG_ ST_pwr12V_19 : 24|1@1+ (1,0) [0|1] ""  MBMU,PC
 SG_ ST_pwr5V_19 : 25|1@1+ (1,0) [0|1] ""  MBMU,PC
 SG_ ST_pwr24V_19 : 26|1@1+ (1,0) [0|1] ""  MBMU,PC
 SG_ ST_pwrStatus_19 : 27|3@1+ (1,0) [0|7] ""  MBMU,PC
 SG_ S2A_S2_FullChgFlgFromSBMU_19 : 30|8@1+ (1,0) [0|255] ""  MBMU,PC
 SG_ ST_cscStandby_19 : 46|2@1+ (1,0) [0|3] ""  MBMU,PC
 SG_ ST_OffReasonMsg_19 : 48|16@1+ (1,0) [0|65535] ""  MBMU,PC

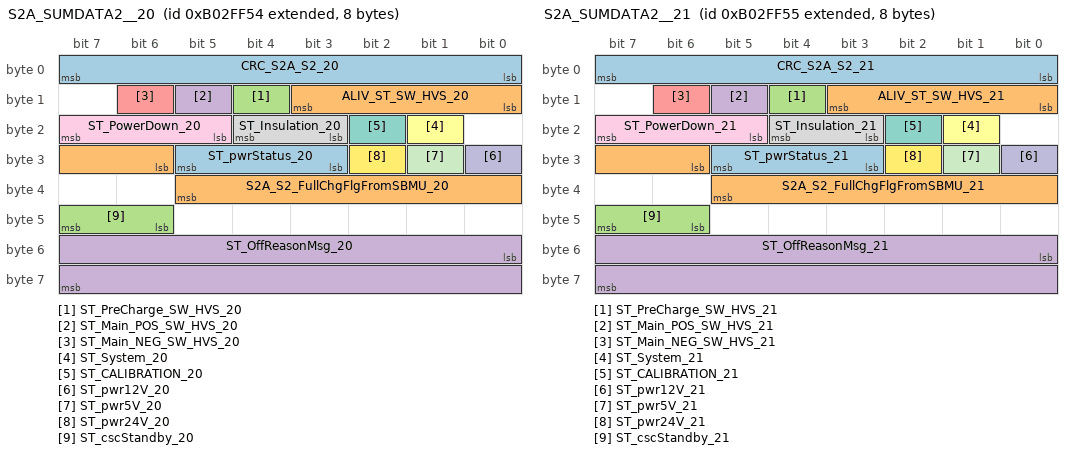
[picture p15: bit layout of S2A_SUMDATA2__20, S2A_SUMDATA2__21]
BO_ 2332229460 S2A_SUMDATA2__20: 8 SBMU
 SG_ CRC_S2A_S2_20 : 0|8@1+ (1,0) [0|255] ""  MBMU,PC
 SG_ ALIV_ST_SW_HVS_20 : 8|4@1+ (1,0) [0|15] ""  MBMU,PC
 SG_ ST_PreCharge_SW_HVS_20 : 12|1@1+ (1,0) [0|1] ""  MBMU,PC
 SG_ ST_Main_POS_SW_HVS_20 : 13|1@1+ (1,0) [0|1] ""  MBMU,PC
 SG_ ST_Main_NEG_SW_HVS_20 : 14|1@1+ (1,0) [0|1] ""  MBMU,PC
 SG_ ST_System_20 : 17|1@1+ (1,0) [0|1] ""  MBMU,PC
 SG_ ST_CALIBRATION_20 : 18|1@1+ (1,0) [0|1] ""  MBMU,PC
 SG_ ST_Insulation_20 : 19|2@1+ (1,0) [0|3] ""  MBMU,PC
 SG_ ST_PowerDown_20 : 21|3@1+ (1,0) [0|7] ""  MBMU,PC
 SG_ ST_pwr12V_20 : 24|1@1+ (1,0) [0|1] ""  MBMU,PC
 SG_ ST_pwr5V_20 : 25|1@1+ (1,0) [0|1] ""  MBMU,PC
 SG_ ST_pwr24V_20 : 26|1@1+ (1,0) [0|1] ""  MBMU,PC
 SG_ ST_pwrStatus_20 : 27|3@1+ (1,0) [0|7] ""  MBMU,PC
 SG_ S2A_S2_FullChgFlgFromSBMU_20 : 30|8@1+ (1,0) [0|255] ""  MBMU,PC
 SG_ ST_cscStandby_20 : 46|2@1+ (1,0) [0|3] ""  MBMU,PC
 SG_ ST_OffReasonMsg_20 : 48|16@1+ (1,0) [0|65535] ""  MBMU,PC

BO_ 2332229461 S2A_SUMDATA2__21: 8 SBMU
 SG_ CRC_S2A_S2_21 : 0|8@1+ (1,0) [0|255] ""  MBMU,PC
 SG_ ALIV_ST_SW_HVS_21 : 8|4@1+ (1,0) [0|15] ""  MBMU,PC
 SG_ ST_PreCharge_SW_HVS_21 : 12|1@1+ (1,0) [0|1] ""  MBMU,PC
 SG_ ST_Main_POS_SW_HVS_21 : 13|1@1+ (1,0) [0|1] ""  MBMU,PC
 SG_ ST_Main_NEG_SW_HVS_21 : 14|1@1+ (1,0) [0|1] ""  MBMU,PC
 SG_ ST_System_21 : 17|1@1+ (1,0) [0|1] ""  MBMU,PC
 SG_ ST_CALIBRATION_21 : 18|1@1+ (1,0) [0|1] ""  MBMU,PC
 SG_ ST_Insulation_21 : 19|2@1+ (1,0) [0|3] ""  MBMU,PC
 SG_ ST_PowerDown_21 : 21|3@1+ (1,0) [0|7] ""  MBMU,PC
 SG_ ST_pwr12V_21 : 24|1@1+ (1,0) [0|1] ""  MBMU,PC
 SG_ ST_pwr5V_21 : 25|1@1+ (1,0) [0|1] ""  MBMU,PC
 SG_ ST_pwr24V_21 : 26|1@1+ (1,0) [0|1] ""  MBMU,PC
 SG_ ST_pwrStatus_21 : 27|3@1+ (1,0) [0|7] ""  MBMU,PC
 SG_ S2A_S2_FullChgFlgFromSBMU_21 : 30|8@1+ (1,0) [0|255] ""  MBMU,PC
 SG_ ST_cscStandby_21 : 46|2@1+ (1,0) [0|3] ""  MBMU,PC
 SG_ ST_OffReasonMsg_21 : 48|16@1+ (1,0) [0|65535] ""  MBMU,PC

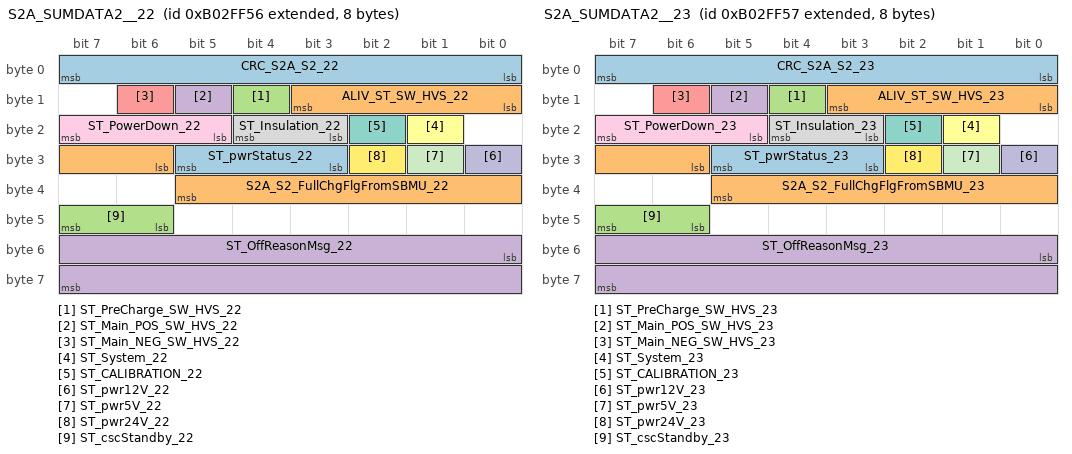
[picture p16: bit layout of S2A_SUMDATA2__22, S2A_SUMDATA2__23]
BO_ 2332229462 S2A_SUMDATA2__22: 8 SBMU
 SG_ CRC_S2A_S2_22 : 0|8@1+ (1,0) [0|255] ""  MBMU,PC
 SG_ ALIV_ST_SW_HVS_22 : 8|4@1+ (1,0) [0|15] ""  MBMU,PC
 SG_ ST_PreCharge_SW_HVS_22 : 12|1@1+ (1,0) [0|1] ""  MBMU,PC
 SG_ ST_Main_POS_SW_HVS_22 : 13|1@1+ (1,0) [0|1] ""  MBMU,PC
 SG_ ST_Main_NEG_SW_HVS_22 : 14|1@1+ (1,0) [0|1] ""  MBMU,PC
 SG_ ST_System_22 : 17|1@1+ (1,0) [0|1] ""  MBMU,PC
 SG_ ST_CALIBRATION_22 : 18|1@1+ (1,0) [0|1] ""  MBMU,PC
 SG_ ST_Insulation_22 : 19|2@1+ (1,0) [0|3] ""  MBMU,PC
 SG_ ST_PowerDown_22 : 21|3@1+ (1,0) [0|7] ""  MBMU,PC
 SG_ ST_pwr12V_22 : 24|1@1+ (1,0) [0|1] ""  MBMU,PC
 SG_ ST_pwr5V_22 : 25|1@1+ (1,0) [0|1] ""  MBMU,PC
 SG_ ST_pwr24V_22 : 26|1@1+ (1,0) [0|1] ""  MBMU,PC
 SG_ ST_pwrStatus_22 : 27|3@1+ (1,0) [0|7] ""  MBMU,PC
 SG_ S2A_S2_FullChgFlgFromSBMU_22 : 30|8@1+ (1,0) [0|255] ""  MBMU,PC
 SG_ ST_cscStandby_22 : 46|2@1+ (1,0) [0|3] ""  MBMU,PC
 SG_ ST_OffReasonMsg_22 : 48|16@1+ (1,0) [0|65535] ""  MBMU,PC

BO_ 2332229463 S2A_SUMDATA2__23: 8 SBMU
 SG_ CRC_S2A_S2_23 : 0|8@1+ (1,0) [0|255] ""  MBMU,PC
 SG_ ALIV_ST_SW_HVS_23 : 8|4@1+ (1,0) [0|15] ""  MBMU,PC
 SG_ ST_PreCharge_SW_HVS_23 : 12|1@1+ (1,0) [0|1] ""  MBMU,PC
 SG_ ST_Main_POS_SW_HVS_23 : 13|1@1+ (1,0) [0|1] ""  MBMU,PC
 SG_ ST_Main_NEG_SW_HVS_23 : 14|1@1+ (1,0) [0|1] ""  MBMU,PC
 SG_ ST_System_23 : 17|1@1+ (1,0) [0|1] ""  MBMU,PC
 SG_ ST_CALIBRATION_23 : 18|1@1+ (1,0) [0|1] ""  MBMU,PC
 SG_ ST_Insulation_23 : 19|2@1+ (1,0) [0|3] ""  MBMU,PC
 SG_ ST_PowerDown_23 : 21|3@1+ (1,0) [0|7] ""  MBMU,PC
 SG_ ST_pwr12V_23 : 24|1@1+ (1,0) [0|1] ""  MBMU,PC
 SG_ ST_pwr5V_23 : 25|1@1+ (1,0) [0|1] ""  MBMU,PC
 SG_ ST_pwr24V_23 : 26|1@1+ (1,0) [0|1] ""  MBMU,PC
 SG_ ST_pwrStatus_23 : 27|3@1+ (1,0) [0|7] ""  MBMU,PC
 SG_ S2A_S2_FullChgFlgFromSBMU_23 : 30|8@1+ (1,0) [0|255] ""  MBMU,PC
 SG_ ST_cscStandby_23 : 46|2@1+ (1,0) [0|3] ""  MBMU,PC
 SG_ ST_OffReasonMsg_23 : 48|16@1+ (1,0) [0|65535] ""  MBMU,PC

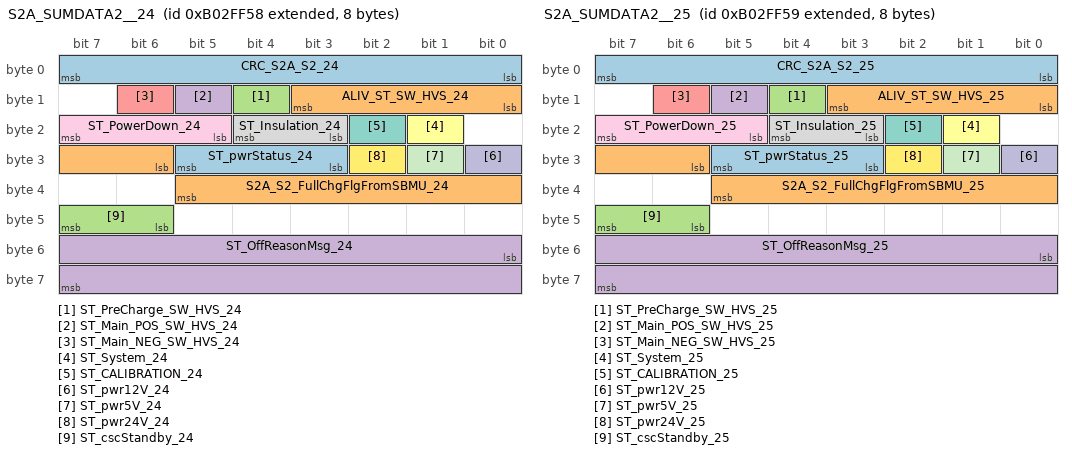
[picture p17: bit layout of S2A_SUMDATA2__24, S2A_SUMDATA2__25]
BO_ 2332229464 S2A_SUMDATA2__24: 8 SBMU
 SG_ CRC_S2A_S2_24 : 0|8@1+ (1,0) [0|255] ""  MBMU,PC
 SG_ ALIV_ST_SW_HVS_24 : 8|4@1+ (1,0) [0|15] ""  MBMU,PC
 SG_ ST_PreCharge_SW_HVS_24 : 12|1@1+ (1,0) [0|1] ""  MBMU,PC
 SG_ ST_Main_POS_SW_HVS_24 : 13|1@1+ (1,0) [0|1] ""  MBMU,PC
 SG_ ST_Main_NEG_SW_HVS_24 : 14|1@1+ (1,0) [0|1] ""  MBMU,PC
 SG_ ST_System_24 : 17|1@1+ (1,0) [0|1] ""  MBMU,PC
 SG_ ST_CALIBRATION_24 : 18|1@1+ (1,0) [0|1] ""  MBMU,PC
 SG_ ST_Insulation_24 : 19|2@1+ (1,0) [0|3] ""  MBMU,PC
 SG_ ST_PowerDown_24 : 21|3@1+ (1,0) [0|7] ""  MBMU,PC
 SG_ ST_pwr12V_24 : 24|1@1+ (1,0) [0|1] ""  MBMU,PC
 SG_ ST_pwr5V_24 : 25|1@1+ (1,0) [0|1] ""  MBMU,PC
 SG_ ST_pwr24V_24 : 26|1@1+ (1,0) [0|1] ""  MBMU,PC
 SG_ ST_pwrStatus_24 : 27|3@1+ (1,0) [0|7] ""  MBMU,PC
 SG_ S2A_S2_FullChgFlgFromSBMU_24 : 30|8@1+ (1,0) [0|255] ""  MBMU,PC
 SG_ ST_cscStandby_24 : 46|2@1+ (1,0) [0|3] ""  MBMU,PC
 SG_ ST_OffReasonMsg_24 : 48|16@1+ (1,0) [0|65535] ""  MBMU,PC

BO_ 2332229465 S2A_SUMDATA2__25: 8 SBMU
 SG_ CRC_S2A_S2_25 : 0|8@1+ (1,0) [0|255] ""  MBMU,PC
 SG_ ALIV_ST_SW_HVS_25 : 8|4@1+ (1,0) [0|15] ""  MBMU,PC
 SG_ ST_PreCharge_SW_HVS_25 : 12|1@1+ (1,0) [0|1] ""  MBMU,PC
 SG_ ST_Main_POS_SW_HVS_25 : 13|1@1+ (1,0) [0|1] ""  MBMU,PC
 SG_ ST_Main_NEG_SW_HVS_25 : 14|1@1+ (1,0) [0|1] ""  MBMU,PC
 SG_ ST_System_25 : 17|1@1+ (1,0) [0|1] ""  MBMU,PC
 SG_ ST_CALIBRATION_25 : 18|1@1+ (1,0) [0|1] ""  MBMU,PC
 SG_ ST_Insulation_25 : 19|2@1+ (1,0) [0|3] ""  MBMU,PC
 SG_ ST_PowerDown_25 : 21|3@1+ (1,0) [0|7] ""  MBMU,PC
 SG_ ST_pwr12V_25 : 24|1@1+ (1,0) [0|1] ""  MBMU,PC
 SG_ ST_pwr5V_25 : 25|1@1+ (1,0) [0|1] ""  MBMU,PC
 SG_ ST_pwr24V_25 : 26|1@1+ (1,0) [0|1] ""  MBMU,PC
 SG_ ST_pwrStatus_25 : 27|3@1+ (1,0) [0|7] ""  MBMU,PC
 SG_ S2A_S2_FullChgFlgFromSBMU_25 : 30|8@1+ (1,0) [0|255] ""  MBMU,PC
 SG_ ST_cscStandby_25 : 46|2@1+ (1,0) [0|3] ""  MBMU,PC
 SG_ ST_OffReasonMsg_25 : 48|16@1+ (1,0) [0|65535] ""  MBMU,PC

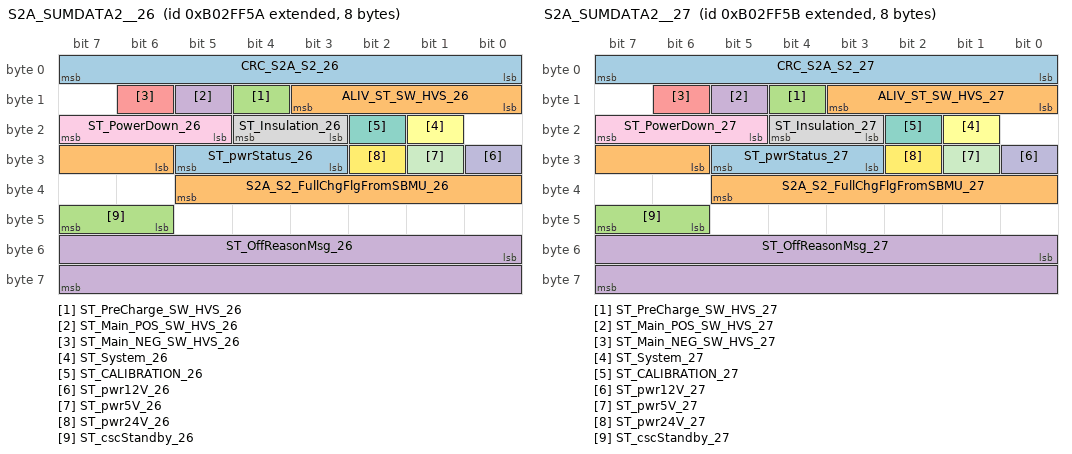
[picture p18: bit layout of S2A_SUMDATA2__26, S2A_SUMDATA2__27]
BO_ 2332229466 S2A_SUMDATA2__26: 8 SBMU
 SG_ CRC_S2A_S2_26 : 0|8@1+ (1,0) [0|255] ""  MBMU,PC
 SG_ ALIV_ST_SW_HVS_26 : 8|4@1+ (1,0) [0|15] ""  MBMU,PC
 SG_ ST_PreCharge_SW_HVS_26 : 12|1@1+ (1,0) [0|1] ""  MBMU,PC
 SG_ ST_Main_POS_SW_HVS_26 : 13|1@1+ (1,0) [0|1] ""  MBMU,PC
 SG_ ST_Main_NEG_SW_HVS_26 : 14|1@1+ (1,0) [0|1] ""  MBMU,PC
 SG_ ST_System_26 : 17|1@1+ (1,0) [0|1] ""  MBMU,PC
 SG_ ST_CALIBRATION_26 : 18|1@1+ (1,0) [0|1] ""  MBMU,PC
 SG_ ST_Insulation_26 : 19|2@1+ (1,0) [0|3] ""  MBMU,PC
 SG_ ST_PowerDown_26 : 21|3@1+ (1,0) [0|7] ""  MBMU,PC
 SG_ ST_pwr12V_26 : 24|1@1+ (1,0) [0|1] ""  MBMU,PC
 SG_ ST_pwr5V_26 : 25|1@1+ (1,0) [0|1] ""  MBMU,PC
 SG_ ST_pwr24V_26 : 26|1@1+ (1,0) [0|1] ""  MBMU,PC
 SG_ ST_pwrStatus_26 : 27|3@1+ (1,0) [0|7] ""  MBMU,PC
 SG_ S2A_S2_FullChgFlgFromSBMU_26 : 30|8@1+ (1,0) [0|255] ""  MBMU,PC
 SG_ ST_cscStandby_26 : 46|2@1+ (1,0) [0|3] ""  MBMU,PC
 SG_ ST_OffReasonMsg_26 : 48|16@1+ (1,0) [0|65535] ""  MBMU,PC

BO_ 2332229467 S2A_SUMDATA2__27: 8 SBMU
 SG_ CRC_S2A_S2_27 : 0|8@1+ (1,0) [0|255] ""  MBMU,PC
 SG_ ALIV_ST_SW_HVS_27 : 8|4@1+ (1,0) [0|15] ""  MBMU,PC
 SG_ ST_PreCharge_SW_HVS_27 : 12|1@1+ (1,0) [0|1] ""  MBMU,PC
 SG_ ST_Main_POS_SW_HVS_27 : 13|1@1+ (1,0) [0|1] ""  MBMU,PC
 SG_ ST_Main_NEG_SW_HVS_27 : 14|1@1+ (1,0) [0|1] ""  MBMU,PC
 SG_ ST_System_27 : 17|1@1+ (1,0) [0|1] ""  MBMU,PC
 SG_ ST_CALIBRATION_27 : 18|1@1+ (1,0) [0|1] ""  MBMU,PC
 SG_ ST_Insulation_27 : 19|2@1+ (1,0) [0|3] ""  MBMU,PC
 SG_ ST_PowerDown_27 : 21|3@1+ (1,0) [0|7] ""  MBMU,PC
 SG_ ST_pwr12V_27 : 24|1@1+ (1,0) [0|1] ""  MBMU,PC
 SG_ ST_pwr5V_27 : 25|1@1+ (1,0) [0|1] ""  MBMU,PC
 SG_ ST_pwr24V_27 : 26|1@1+ (1,0) [0|1] ""  MBMU,PC
 SG_ ST_pwrStatus_27 : 27|3@1+ (1,0) [0|7] ""  MBMU,PC
 SG_ S2A_S2_FullChgFlgFromSBMU_27 : 30|8@1+ (1,0) [0|255] ""  MBMU,PC
 SG_ ST_cscStandby_27 : 46|2@1+ (1,0) [0|3] ""  MBMU,PC
 SG_ ST_OffReasonMsg_27 : 48|16@1+ (1,0) [0|65535] ""  MBMU,PC

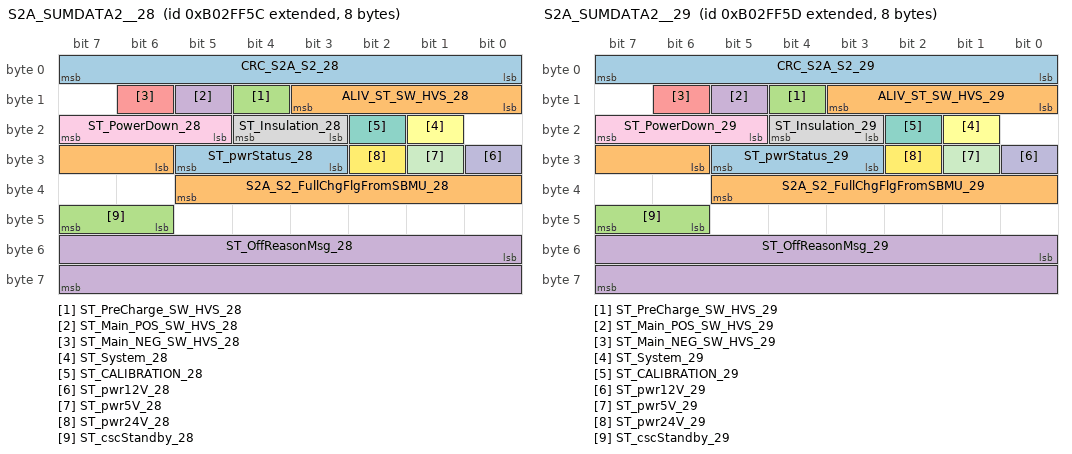
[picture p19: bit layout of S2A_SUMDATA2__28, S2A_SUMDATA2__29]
BO_ 2332229468 S2A_SUMDATA2__28: 8 SBMU
 SG_ CRC_S2A_S2_28 : 0|8@1+ (1,0) [0|255] ""  MBMU,PC
 SG_ ALIV_ST_SW_HVS_28 : 8|4@1+ (1,0) [0|15] ""  MBMU,PC
 SG_ ST_PreCharge_SW_HVS_28 : 12|1@1+ (1,0) [0|1] ""  MBMU,PC
 SG_ ST_Main_POS_SW_HVS_28 : 13|1@1+ (1,0) [0|1] ""  MBMU,PC
 SG_ ST_Main_NEG_SW_HVS_28 : 14|1@1+ (1,0) [0|1] ""  MBMU,PC
 SG_ ST_System_28 : 17|1@1+ (1,0) [0|1] ""  MBMU,PC
 SG_ ST_CALIBRATION_28 : 18|1@1+ (1,0) [0|1] ""  MBMU,PC
 SG_ ST_Insulation_28 : 19|2@1+ (1,0) [0|3] ""  MBMU,PC
 SG_ ST_PowerDown_28 : 21|3@1+ (1,0) [0|7] ""  MBMU,PC
 SG_ ST_pwr12V_28 : 24|1@1+ (1,0) [0|1] ""  MBMU,PC
 SG_ ST_pwr5V_28 : 25|1@1+ (1,0) [0|1] ""  MBMU,PC
 SG_ ST_pwr24V_28 : 26|1@1+ (1,0) [0|1] ""  MBMU,PC
 SG_ ST_pwrStatus_28 : 27|3@1+ (1,0) [0|7] ""  MBMU,PC
 SG_ S2A_S2_FullChgFlgFromSBMU_28 : 30|8@1+ (1,0) [0|255] ""  MBMU,PC
 SG_ ST_cscStandby_28 : 46|2@1+ (1,0) [0|3] ""  MBMU,PC
 SG_ ST_OffReasonMsg_28 : 48|16@1+ (1,0) [0|65535] ""  MBMU,PC

BO_ 2332229469 S2A_SUMDATA2__29: 8 SBMU
 SG_ CRC_S2A_S2_29 : 0|8@1+ (1,0) [0|255] ""  MBMU,PC
 SG_ ALIV_ST_SW_HVS_29 : 8|4@1+ (1,0) [0|15] ""  MBMU,PC
 SG_ ST_PreCharge_SW_HVS_29 : 12|1@1+ (1,0) [0|1] ""  MBMU,PC
 SG_ ST_Main_POS_SW_HVS_29 : 13|1@1+ (1,0) [0|1] ""  MBMU,PC
 SG_ ST_Main_NEG_SW_HVS_29 : 14|1@1+ (1,0) [0|1] ""  MBMU,PC
 SG_ ST_System_29 : 17|1@1+ (1,0) [0|1] ""  MBMU,PC
 SG_ ST_CALIBRATION_29 : 18|1@1+ (1,0) [0|1] ""  MBMU,PC
 SG_ ST_Insulation_29 : 19|2@1+ (1,0) [0|3] ""  MBMU,PC
 SG_ ST_PowerDown_29 : 21|3@1+ (1,0) [0|7] ""  MBMU,PC
 SG_ ST_pwr12V_29 : 24|1@1+ (1,0) [0|1] ""  MBMU,PC
 SG_ ST_pwr5V_29 : 25|1@1+ (1,0) [0|1] ""  MBMU,PC
 SG_ ST_pwr24V_29 : 26|1@1+ (1,0) [0|1] ""  MBMU,PC
 SG_ ST_pwrStatus_29 : 27|3@1+ (1,0) [0|7] ""  MBMU,PC
 SG_ S2A_S2_FullChgFlgFromSBMU_29 : 30|8@1+ (1,0) [0|255] ""  MBMU,PC
 SG_ ST_cscStandby_29 : 46|2@1+ (1,0) [0|3] ""  MBMU,PC
 SG_ ST_OffReasonMsg_29 : 48|16@1+ (1,0) [0|65535] ""  MBMU,PC

CM_ SG_ 2265055041 S2A_AL_Fault_Page_01 "故障码页";
CM_ SG_ 2265055041 S2A_AL_Fault_Number1_01 "故障码1";
CM_ SG_ 2265055041 S2A_AL_Fault_Number2_01 "故障码2";
CM_ SG_ 2265055041 S2A_AL_Fault_Number3_01 "故障码3";
CM_ SG_ 2265055041 S2A_AL_Fault_Number4_01 "故障码4";
CM_ SG_ 2265055041 S2A_AL_Fault_Number5_01 "故障码5";
CM_ SG_ 2265055041 S2A_AL_Fault_Number6_01 "故障码6";
CM_ SG_ 2265055042 S2A_AL_Fault_Page_02 "故障码页";
CM_ SG_ 2265055042 S2A_AL_Fault_Number1_02 "故障码1";
CM_ SG_ 2265055042 S2A_AL_Fault_Number2_02 "故障码2";
CM_ SG_ 2265055042 S2A_AL_Fault_Number3_02 "故障码3";
CM_ SG_ 2265055042 S2A_AL_Fault_Number4_02 "故障码4";
CM_ SG_ 2265055042 S2A_AL_Fault_Number5_02 "故障码5";
CM_ SG_ 2265055042 S2A_AL_Fault_Number6_02 "故障码6";
CM_ SG_ 2265055043 S2A_AL_Fault_Page_03 "故障码页";
CM_ SG_ 2265055043 S2A_AL_Fault_Number1_03 "故障码1";
CM_ SG_ 2265055043 S2A_AL_Fault_Number2_03 "故障码2";
CM_ SG_ 2265055043 S2A_AL_Fault_Number3_03 "故障码3";
CM_ SG_ 2265055043 S2A_AL_Fault_Number4_03 "故障码4";
CM_ SG_ 2265055043 S2A_AL_Fault_Number5_03 "故障码5";
CM_ SG_ 2265055043 S2A_AL_Fault_Number6_03 "故障码6";
CM_ SG_ 2265055044 S2A_AL_Fault_Page_04 "故障码页";
CM_ SG_ 2265055044 S2A_AL_Fault_Number1_04 "故障码1";
CM_ SG_ 2265055044 S2A_AL_Fault_Number2_04 "故障码2";
CM_ SG_ 2265055044 S2A_AL_Fault_Number3_04 "故障码3";
CM_ SG_ 2265055044 S2A_AL_Fault_Number4_04 "故障码4";
CM_ SG_ 2265055044 S2A_AL_Fault_Number5_04 "故障码5";
CM_ SG_ 2265055044 S2A_AL_Fault_Number6_04 "故障码6";
CM_ SG_ 2265055045 S2A_AL_Fault_Page_05 "故障码页";
CM_ SG_ 2265055045 S2A_AL_Fault_Number1_05 "故障码1";
CM_ SG_ 2265055045 S2A_AL_Fault_Number2_05 "故障码2";
CM_ SG_ 2265055045 S2A_AL_Fault_Number3_05 "故障码3";
CM_ SG_ 2265055045 S2A_AL_Fault_Number4_05 "故障码4";
CM_ SG_ 2265055045 S2A_AL_Fault_Number5_05 "故障码5";
CM_ SG_ 2265055045 S2A_AL_Fault_Number6_05 "故障码6";
CM_ SG_ 2265055046 S2A_AL_Fault_Page_06 "故障码页";
CM_ SG_ 2265055046 S2A_AL_Fault_Number1_06 "故障码1";
CM_ SG_ 2265055046 S2A_AL_Fault_Number2_06 "故障码2";
CM_ SG_ 2265055046 S2A_AL_Fault_Number3_06 "故障码3";
CM_ SG_ 2265055046 S2A_AL_Fault_Number4_06 "故障码4";
CM_ SG_ 2265055046 S2A_AL_Fault_Number5_06 "故障码5";
CM_ SG_ 2265055046 S2A_AL_Fault_Number6_06 "故障码6";
CM_ SG_ 2265055047 S2A_AL_Fault_Page_07 "故障码页";
CM_ SG_ 2265055047 S2A_AL_Fault_Number1_07 "故障码1";
CM_ SG_ 2265055047 S2A_AL_Fault_Number2_07 "故障码2";
CM_ SG_ 2265055047 S2A_AL_Fault_Number3_07 "故障码3";
CM_ SG_ 2265055047 S2A_AL_Fault_Number4_07 "故障码4";
CM_ SG_ 2265055047 S2A_AL_Fault_Number5_07 "故障码5";
CM_ SG_ 2265055047 S2A_AL_Fault_Number6_07 "故障码6";
CM_ SG_ 2265055048 S2A_AL_Fault_Page_08 "故障码页";
CM_ SG_ 2265055048 S2A_AL_Fault_Number1_08 "故障码1";
CM_ SG_ 2265055048 S2A_AL_Fault_Number2_08 "故障码2";
CM_ SG_ 2265055048 S2A_AL_Fault_Number3_08 "故障码3";
CM_ SG_ 2265055048 S2A_AL_Fault_Number4_08 "故障码4";
CM_ SG_ 2265055048 S2A_AL_Fault_Number5_08 "故障码5";
CM_ SG_ 2265055048 S2A_AL_Fault_Number6_08 "故障码6";
CM_ SG_ 2265055049 S2A_AL_Fault_Page_09 "故障码页";
CM_ SG_ 2265055049 S2A_AL_Fault_Number1_09 "故障码1";
CM_ SG_ 2265055049 S2A_AL_Fault_Number2_09 "故障码2";
CM_ SG_ 2265055049 S2A_AL_Fault_Number3_09 "故障码3";
CM_ SG_ 2265055049 S2A_AL_Fault_Number4_09 "故障码4";
CM_ SG_ 2265055049 S2A_AL_Fault_Number5_09 "故障码5";
CM_ SG_ 2265055049 S2A_AL_Fault_Number6_09 "故障码6";
CM_ SG_ 2265055050 S2A_AL_Fault_Page_10 "故障码页";
CM_ SG_ 2265055050 S2A_AL_Fault_Number1_10 "故障码1";
CM_ SG_ 2265055050 S2A_AL_Fault_Number2_10 "故障码2";
CM_ SG_ 2265055050 S2A_AL_Fault_Number3_10 "故障码3";
CM_ SG_ 2265055050 S2A_AL_Fault_Number4_10 "故障码4";
CM_ SG_ 2265055050 S2A_AL_Fault_Number5_10 "故障码5";
CM_ SG_ 2265055050 S2A_AL_Fault_Number6_10 "故障码6";
CM_ SG_ 2265055051 S2A_AL_Fault_Page_11 "故障码页";
CM_ SG_ 2265055051 S2A_AL_Fault_Number1_11 "故障码1";
CM_ SG_ 2265055051 S2A_AL_Fault_Number2_11 "故障码2";
CM_ SG_ 2265055051 S2A_AL_Fault_Number3_11 "故障码3";
CM_ SG_ 2265055051 S2A_AL_Fault_Number4_11 "故障码4";
CM_ SG_ 2265055051 S2A_AL_Fault_Number5_11 "故障码5";
CM_ SG_ 2265055051 S2A_AL_Fault_Number6_11 "故障码6";
CM_ SG_ 2265055052 S2A_AL_Fault_Page_12 "故障码页";
CM_ SG_ 2265055052 S2A_AL_Fault_Number1_12 "故障码1";
CM_ SG_ 2265055052 S2A_AL_Fault_Number2_12 "故障码2";
CM_ SG_ 2265055052 S2A_AL_Fault_Number3_12 "故障码3";
CM_ SG_ 2265055052 S2A_AL_Fault_Number4_12 "故障码4";
CM_ SG_ 2265055052 S2A_AL_Fault_Number5_12 "故障码5";
CM_ SG_ 2265055052 S2A_AL_Fault_Number6_12 "故障码6";
CM_ SG_ 2265055053 S2A_AL_Fault_Page_13 "故障码页";
CM_ SG_ 2265055053 S2A_AL_Fault_Number1_13 "故障码1";
CM_ SG_ 2265055053 S2A_AL_Fault_Number2_13 "故障码2";
CM_ SG_ 2265055053 S2A_AL_Fault_Number3_13 "故障码3";
CM_ SG_ 2265055053 S2A_AL_Fault_Number4_13 "故障码4";
CM_ SG_ 2265055053 S2A_AL_Fault_Number5_13 "故障码5";
CM_ SG_ 2265055053 S2A_AL_Fault_Number6_13 "故障码6";
CM_ SG_ 2265055054 S2A_AL_Fault_Page_14 "故障码页";
CM_ SG_ 2265055054 S2A_AL_Fault_Number1_14 "故障码1";
CM_ SG_ 2265055054 S2A_AL_Fault_Number2_14 "故障码2";
CM_ SG_ 2265055054 S2A_AL_Fault_Number3_14 "故障码3";
CM_ SG_ 2265055054 S2A_AL_Fault_Number4_14 "故障码4";
CM_ SG_ 2265055054 S2A_AL_Fault_Number5_14 "故障码5";
CM_ SG_ 2265055054 S2A_AL_Fault_Number6_14 "故障码6";
CM_ SG_ 2265055055 S2A_AL_Fault_Page_15 "故障码页";
CM_ SG_ 2265055055 S2A_AL_Fault_Number1_15 "故障码1";
CM_ SG_ 2265055055 S2A_AL_Fault_Number2_15 "故障码2";
CM_ SG_ 2265055055 S2A_AL_Fault_Number3_15 "故障码3";
CM_ SG_ 2265055055 S2A_AL_Fault_Number4_15 "故障码4";
CM_ SG_ 2265055055 S2A_AL_Fault_Number5_15 "故障码5";
CM_ SG_ 2265055055 S2A_AL_Fault_Number6_15 "故障码6";
CM_ SG_ 2265055056 S2A_AL_Fault_Page_16 "故障码页";
CM_ SG_ 2265055056 S2A_AL_Fault_Number1_16 "故障码1";
CM_ SG_ 2265055056 S2A_AL_Fault_Number2_16 "故障码2";
CM_ SG_ 2265055056 S2A_AL_Fault_Number3_16 "故障码3";
CM_ SG_ 2265055056 S2A_AL_Fault_Number4_16 "故障码4";
CM_ SG_ 2265055056 S2A_AL_Fault_Number5_16 "故障码5";
CM_ SG_ 2265055056 S2A_AL_Fault_Number6_16 "故障码6";
CM_ SG_ 2265055057 S2A_AL_Fault_Page_17 "故障码页";
CM_ SG_ 2265055057 S2A_AL_Fault_Number1_17 "故障码1";
CM_ SG_ 2265055057 S2A_AL_Fault_Number2_17 "故障码2";
CM_ SG_ 2265055057 S2A_AL_Fault_Number3_17 "故障码3";
CM_ SG_ 2265055057 S2A_AL_Fault_Number4_17 "故障码4";
CM_ SG_ 2265055057 S2A_AL_Fault_Number5_17 "故障码5";
CM_ SG_ 2265055057 S2A_AL_Fault_Number6_17 "故障码6";
CM_ SG_ 2265055058 S2A_AL_Fault_Page_18 "故障码页";
CM_ SG_ 2265055058 S2A_AL_Fault_Number1_18 "故障码1";
CM_ SG_ 2265055058 S2A_AL_Fault_Number2_18 "故障码2";
CM_ SG_ 2265055058 S2A_AL_Fault_Number3_18 "故障码3";
CM_ SG_ 2265055058 S2A_AL_Fault_Number4_18 "故障码4";
CM_ SG_ 2265055058 S2A_AL_Fault_Number5_18 "故障码5";
CM_ SG_ 2265055058 S2A_AL_Fault_Number6_18 "故障码6";
CM_ SG_ 2265055059 S2A_AL_Fault_Page_19 "故障码页";
CM_ SG_ 2265055059 S2A_AL_Fault_Number1_19 "故障码1";
CM_ SG_ 2265055059 S2A_AL_Fault_Number2_19 "故障码2";
CM_ SG_ 2265055059 S2A_AL_Fault_Number3_19 "故障码3";
CM_ SG_ 2265055059 S2A_AL_Fault_Number4_19 "故障码4";
CM_ SG_ 2265055059 S2A_AL_Fault_Number5_19 "故障码5";
CM_ SG_ 2265055059 S2A_AL_Fault_Number6_19 "故障码6";
CM_ SG_ 2265055060 S2A_AL_Fault_Page_20 "故障码页";
CM_ SG_ 2265055060 S2A_AL_Fault_Number1_20 "故障码1";
CM_ SG_ 2265055060 S2A_AL_Fault_Number2_20 "故障码2";
CM_ SG_ 2265055060 S2A_AL_Fault_Number3_20 "故障码3";
CM_ SG_ 2265055060 S2A_AL_Fault_Number4_20 "故障码4";
CM_ SG_ 2265055060 S2A_AL_Fault_Number5_20 "故障码5";
CM_ SG_ 2265055060 S2A_AL_Fault_Number6_20 "故障码6";
CM_ SG_ 2265055061 S2A_AL_Fault_Page_21 "故障码页";
CM_ SG_ 2265055061 S2A_AL_Fault_Number1_21 "故障码1";
CM_ SG_ 2265055061 S2A_AL_Fault_Number2_21 "故障码2";
CM_ SG_ 2265055061 S2A_AL_Fault_Number3_21 "故障码3";
CM_ SG_ 2265055061 S2A_AL_Fault_Number4_21 "故障码4";
CM_ SG_ 2265055061 S2A_AL_Fault_Number5_21 "故障码5";
CM_ SG_ 2265055061 S2A_AL_Fault_Number6_21 "故障码6";
CM_ SG_ 2265055062 S2A_AL_Fault_Page_22 "故障码页";
CM_ SG_ 2265055062 S2A_AL_Fault_Number1_22 "故障码1";
CM_ SG_ 2265055062 S2A_AL_Fault_Number2_22 "故障码2";
CM_ SG_ 2265055062 S2A_AL_Fault_Number3_22 "故障码3";
CM_ SG_ 2265055062 S2A_AL_Fault_Number4_22 "故障码4";
CM_ SG_ 2265055062 S2A_AL_Fault_Number5_22 "故障码5";
CM_ SG_ 2265055062 S2A_AL_Fault_Number6_22 "故障码6";
CM_ SG_ 2265055063 S2A_AL_Fault_Page_23 "故障码页";
CM_ SG_ 2265055063 S2A_AL_Fault_Number1_23 "故障码1";
CM_ SG_ 2265055063 S2A_AL_Fault_Number2_23 "故障码2";
CM_ SG_ 2265055063 S2A_AL_Fault_Number3_23 "故障码3";
CM_ SG_ 2265055063 S2A_AL_Fault_Number4_23 "故障码4";
CM_ SG_ 2265055063 S2A_AL_Fault_Number5_23 "故障码5";
CM_ SG_ 2265055063 S2A_AL_Fault_Number6_23 "故障码6";
CM_ SG_ 2265055064 S2A_AL_Fault_Page_24 "故障码页";
CM_ SG_ 2265055064 S2A_AL_Fault_Number1_24 "故障码1";
CM_ SG_ 2265055064 S2A_AL_Fault_Number2_24 "故障码2";
CM_ SG_ 2265055064 S2A_AL_Fault_Number3_24 "故障码3";
CM_ SG_ 2265055064 S2A_AL_Fault_Number4_24 "故障码4";
CM_ SG_ 2265055064 S2A_AL_Fault_Number5_24 "故障码5";
CM_ SG_ 2265055064 S2A_AL_Fault_Number6_24 "故障码6";
CM_ SG_ 2265055065 S2A_AL_Fault_Page_25 "故障码页";
CM_ SG_ 2265055065 S2A_AL_Fault_Number1_25 "故障码1";
CM_ SG_ 2265055065 S2A_AL_Fault_Number2_25 "故障码2";
CM_ SG_ 2265055065 S2A_AL_Fault_Number3_25 "故障码3";
CM_ SG_ 2265055065 S2A_AL_Fault_Number4_25 "故障码4";
CM_ SG_ 2265055065 S2A_AL_Fault_Number5_25 "故障码5";
CM_ SG_ 2265055065 S2A_AL_Fault_Number6_25 "故障码6";
CM_ SG_ 2265055066 S2A_AL_Fault_Page_26 "故障码页";
CM_ SG_ 2265055066 S2A_AL_Fault_Number1_26 "故障码1";
CM_ SG_ 2265055066 S2A_AL_Fault_Number2_26 "故障码2";
CM_ SG_ 2265055066 S2A_AL_Fault_Number3_26 "故障码3";
CM_ SG_ 2265055066 S2A_AL_Fault_Number4_26 "故障码4";
CM_ SG_ 2265055066 S2A_AL_Fault_Number5_26 "故障码5";
CM_ SG_ 2265055066 S2A_AL_Fault_Number6_26 "故障码6";
CM_ SG_ 2265055067 S2A_AL_Fault_Page_27 "故障码页";
CM_ SG_ 2265055067 S2A_AL_Fault_Number1_27 "故障码1";
CM_ SG_ 2265055067 S2A_AL_Fault_Number2_27 "故障码2";
CM_ SG_ 2265055067 S2A_AL_Fault_Number3_27 "故障码3";
CM_ SG_ 2265055067 S2A_AL_Fault_Number4_27 "故障码4";
CM_ SG_ 2265055067 S2A_AL_Fault_Number5_27 "故障码5";
CM_ SG_ 2265055067 S2A_AL_Fault_Number6_27 "故障码6";
CM_ SG_ 2265055068 S2A_AL_Fault_Page_28 "故障码页";
CM_ SG_ 2265055068 S2A_AL_Fault_Number1_28 "故障码1";
CM_ SG_ 2265055068 S2A_AL_Fault_Number2_28 "故障码2";
CM_ SG_ 2265055068 S2A_AL_Fault_Number3_28 "故障码3";
CM_ SG_ 2265055068 S2A_AL_Fault_Number4_28 "故障码4";
CM_ SG_ 2265055068 S2A_AL_Fault_Number5_28 "故障码5";
CM_ SG_ 2265055068 S2A_AL_Fault_Number6_28 "故障码6";
CM_ SG_ 2265055069 S2A_AL_Fault_Page_29 "故障码页";
CM_ SG_ 2265055069 S2A_AL_Fault_Number1_29 "故障码1";
CM_ SG_ 2265055069 S2A_AL_Fault_Number2_29 "故障码2";
CM_ SG_ 2265055069 S2A_AL_Fault_Number3_29 "故障码3";
CM_ SG_ 2265055069 S2A_AL_Fault_Number4_29 "故障码4";
CM_ SG_ 2265055069 S2A_AL_Fault_Number5_29 "故障码5";
CM_ SG_ 2265055069 S2A_AL_Fault_Number6_29 "故障码6";
CM_ SG_ 2265055070 S2A_AL_Fault_Page_30 "故障码页";
CM_ SG_ 2265055070 S2A_AL_Fault_Number1_30 "故障码1";
CM_ SG_ 2265055070 S2A_AL_Fault_Number2_30 "故障码2";
CM_ SG_ 2265055070 S2A_AL_Fault_Number3_30 "故障码3";
CM_ SG_ 2265055070 S2A_AL_Fault_Number4_30 "故障码4";
CM_ SG_ 2265055070 S2A_AL_Fault_Number5_30 "故障码5";
CM_ SG_ 2265055070 S2A_AL_Fault_Number6_30 "故障码6";
CM_ SG_ 2265055071 S2A_AL_Fault_Page_31 "故障码页";
CM_ SG_ 2265055071 S2A_AL_Fault_Number1_31 "故障码1";
CM_ SG_ 2265055071 S2A_AL_Fault_Number2_31 "故障码2";
CM_ SG_ 2265055071 S2A_AL_Fault_Number3_31 "故障码3";
CM_ SG_ 2265055071 S2A_AL_Fault_Number4_31 "故障码4";
CM_ SG_ 2265055071 S2A_AL_Fault_Number5_31 "故障码5";
CM_ SG_ 2265055071 S2A_AL_Fault_Number6_31 "故障码6";
CM_ SG_ 2265055072 S2A_AL_Fault_Page_32 "故障码页";
CM_ SG_ 2265055072 S2A_AL_Fault_Number1_32 "故障码1";
CM_ SG_ 2265055072 S2A_AL_Fault_Number2_32 "故障码2";
CM_ SG_ 2265055072 S2A_AL_Fault_Number3_32 "故障码3";
CM_ SG_ 2265055072 S2A_AL_Fault_Number4_32 "故障码4";
CM_ SG_ 2265055072 S2A_AL_Fault_Number5_32 "故障码5";
CM_ SG_ 2265055072 S2A_AL_Fault_Number6_32 "故障码6";
CM_ SG_ 2265055073 S2A_AL_Fault_Page_33 "故障码页";
CM_ SG_ 2265055073 S2A_AL_Fault_Number1_33 "故障码1";
CM_ SG_ 2265055073 S2A_AL_Fault_Number2_33 "故障码2";
CM_ SG_ 2265055073 S2A_AL_Fault_Number3_33 "故障码3";
CM_ SG_ 2265055073 S2A_AL_Fault_Number4_33 "故障码4";
CM_ SG_ 2265055073 S2A_AL_Fault_Number5_33 "故障码5";
CM_ SG_ 2265055073 S2A_AL_Fault_Number6_33 "故障码6";
CM_ SG_ 2265055074 S2A_AL_Fault_Page_34 "故障码页";
CM_ SG_ 2265055074 S2A_AL_Fault_Number1_34 "故障码1";
CM_ SG_ 2265055074 S2A_AL_Fault_Number2_34 "故障码2";
CM_ SG_ 2265055074 S2A_AL_Fault_Number3_34 "故障码3";
CM_ SG_ 2265055074 S2A_AL_Fault_Number4_34 "故障码4";
CM_ SG_ 2265055074 S2A_AL_Fault_Number5_34 "故障码5";
CM_ SG_ 2265055074 S2A_AL_Fault_Number6_34 "故障码6";
CM_ SG_ 2265055075 S2A_AL_Fault_Page_35 "故障码页";
CM_ SG_ 2265055075 S2A_AL_Fault_Number1_35 "故障码1";
CM_ SG_ 2265055075 S2A_AL_Fault_Number2_35 "故障码2";
CM_ SG_ 2265055075 S2A_AL_Fault_Number3_35 "故障码3";
CM_ SG_ 2265055075 S2A_AL_Fault_Number4_35 "故障码4";
CM_ SG_ 2265055075 S2A_AL_Fault_Number5_35 "故障码5";
CM_ SG_ 2265055075 S2A_AL_Fault_Number6_35 "故障码6";
CM_ SG_ 2265055076 S2A_AL_Fault_Page_36 "故障码页";
CM_ SG_ 2265055076 S2A_AL_Fault_Number1_36 "故障码1";
CM_ SG_ 2265055076 S2A_AL_Fault_Number2_36 "故障码2";
CM_ SG_ 2265055076 S2A_AL_Fault_Number3_36 "故障码3";
CM_ SG_ 2265055076 S2A_AL_Fault_Number4_36 "故障码4";
CM_ SG_ 2265055076 S2A_AL_Fault_Number5_36 "故障码5";
CM_ SG_ 2265055076 S2A_AL_Fault_Number6_36 "故障码6";
CM_ SG_ 2265055077 S2A_AL_Fault_Page_37 "故障码页";
CM_ SG_ 2265055077 S2A_AL_Fault_Number1_37 "故障码1";
CM_ SG_ 2265055077 S2A_AL_Fault_Number2_37 "故障码2";
CM_ SG_ 2265055077 S2A_AL_Fault_Number3_37 "故障码3";
CM_ SG_ 2265055077 S2A_AL_Fault_Number4_37 "故障码4";
CM_ SG_ 2265055077 S2A_AL_Fault_Number5_37 "故障码5";
CM_ SG_ 2265055077 S2A_AL_Fault_Number6_37 "故障码6";
CM_ SG_ 2265055078 S2A_AL_Fault_Page_38 "故障码页";
CM_ SG_ 2265055078 S2A_AL_Fault_Number1_38 "故障码1";
CM_ SG_ 2265055078 S2A_AL_Fault_Number2_38 "故障码2";
CM_ SG_ 2265055078 S2A_AL_Fault_Number3_38 "故障码3";
CM_ SG_ 2265055078 S2A_AL_Fault_Number4_38 "故障码4";
CM_ SG_ 2265055078 S2A_AL_Fault_Number5_38 "故障码5";
CM_ SG_ 2265055078 S2A_AL_Fault_Number6_38 "故障码6";
CM_ SG_ 2265055079 S2A_AL_Fault_Page_39 "故障码页";
CM_ SG_ 2265055079 S2A_AL_Fault_Number1_39 "故障码1";
CM_ SG_ 2265055079 S2A_AL_Fault_Number2_39 "故障码2";
CM_ SG_ 2265055079 S2A_AL_Fault_Number3_39 "故障码3";
CM_ SG_ 2265055079 S2A_AL_Fault_Number4_39 "故障码4";
CM_ SG_ 2265055079 S2A_AL_Fault_Number5_39 "故障码5";
CM_ SG_ 2265055079 S2A_AL_Fault_Number6_39 "故障码6";
CM_ SG_ 2265055080 S2A_AL_Fault_Page_40 "故障码页";
CM_ SG_ 2265055080 S2A_AL_Fault_Number1_40 "故障码1";
CM_ SG_ 2265055080 S2A_AL_Fault_Number2_40 "故障码2";
CM_ SG_ 2265055080 S2A_AL_Fault_Number3_40 "故障码3";
CM_ SG_ 2265055080 S2A_AL_Fault_Number4_40 "故障码4";
CM_ SG_ 2265055080 S2A_AL_Fault_Number5_40 "故障码5";
CM_ SG_ 2265055080 S2A_AL_Fault_Number6_40 "故障码6";
CM_ SG_ 2265055081 S2A_AL_Fault_Page_41 "故障码页";
CM_ SG_ 2265055081 S2A_AL_Fault_Number1_41 "故障码1";
CM_ SG_ 2265055081 S2A_AL_Fault_Number2_41 "故障码2";
CM_ SG_ 2265055081 S2A_AL_Fault_Number3_41 "故障码3";
CM_ SG_ 2265055081 S2A_AL_Fault_Number4_41 "故障码4";
CM_ SG_ 2265055081 S2A_AL_Fault_Number5_41 "故障码5";
CM_ SG_ 2265055081 S2A_AL_Fault_Number6_41 "故障码6";
CM_ SG_ 2265055082 S2A_AL_Fault_Page_42 "故障码页";
CM_ SG_ 2265055082 S2A_AL_Fault_Number1_42 "故障码1";
CM_ SG_ 2265055082 S2A_AL_Fault_Number2_42 "故障码2";
CM_ SG_ 2265055082 S2A_AL_Fault_Number3_42 "故障码3";
CM_ SG_ 2265055082 S2A_AL_Fault_Number4_42 "故障码4";
CM_ SG_ 2265055082 S2A_AL_Fault_Number5_42 "故障码5";
CM_ SG_ 2265055082 S2A_AL_Fault_Number6_42 "故障码6";
CM_ SG_ 2265055083 S2A_AL_Fault_Page_43 "故障码页";
CM_ SG_ 2265055083 S2A_AL_Fault_Number1_43 "故障码1";
CM_ SG_ 2265055083 S2A_AL_Fault_Number2_43 "故障码2";
CM_ SG_ 2265055083 S2A_AL_Fault_Number3_43 "故障码3";
CM_ SG_ 2265055083 S2A_AL_Fault_Number4_43 "故障码4";
CM_ SG_ 2265055083 S2A_AL_Fault_Number5_43 "故障码5";
CM_ SG_ 2265055083 S2A_AL_Fault_Number6_43 "故障码6";
CM_ SG_ 2265055084 S2A_AL_Fault_Page_44 "故障码页";
CM_ SG_ 2265055084 S2A_AL_Fault_Number1_44 "故障码1";
CM_ SG_ 2265055084 S2A_AL_Fault_Number2_44 "故障码2";
CM_ SG_ 2265055084 S2A_AL_Fault_Number3_44 "故障码3";
CM_ SG_ 2265055084 S2A_AL_Fault_Number4_44 "故障码4";
CM_ SG_ 2265055084 S2A_AL_Fault_Number5_44 "故障码5";
CM_ SG_ 2265055084 S2A_AL_Fault_Number6_44 "故障码6";
CM_ SG_ 2265055085 S2A_AL_Fault_Page_45 "故障码页";
CM_ SG_ 2265055085 S2A_AL_Fault_Number1_45 "故障码1";
CM_ SG_ 2265055085 S2A_AL_Fault_Number2_45 "故障码2";
CM_ SG_ 2265055085 S2A_AL_Fault_Number3_45 "故障码3";
CM_ SG_ 2265055085 S2A_AL_Fault_Number4_45 "故障码4";
CM_ SG_ 2265055085 S2A_AL_Fault_Number5_45 "故障码5";
CM_ SG_ 2265055085 S2A_AL_Fault_Number6_45 "故障码6";
CM_ SG_ 2265055086 S2A_AL_Fault_Page_46 "故障码页";
CM_ SG_ 2265055086 S2A_AL_Fault_Number1_46 "故障码1";
CM_ SG_ 2265055086 S2A_AL_Fault_Number2_46 "故障码2";
CM_ SG_ 2265055086 S2A_AL_Fault_Number3_46 "故障码3";
CM_ SG_ 2265055086 S2A_AL_Fault_Number4_46 "故障码4";
CM_ SG_ 2265055086 S2A_AL_Fault_Number5_46 "故障码5";
CM_ SG_ 2265055086 S2A_AL_Fault_Number6_46 "故障码6";
CM_ SG_ 2265055087 S2A_AL_Fault_Page_47 "故障码页";
CM_ SG_ 2265055087 S2A_AL_Fault_Number1_47 "故障码1";
CM_ SG_ 2265055087 S2A_AL_Fault_Number2_47 "故障码2";
CM_ SG_ 2265055087 S2A_AL_Fault_Number3_47 "故障码3";
CM_ SG_ 2265055087 S2A_AL_Fault_Number4_47 "故障码4";
CM_ SG_ 2265055087 S2A_AL_Fault_Number5_47 "故障码5";
CM_ SG_ 2265055087 S2A_AL_Fault_Number6_47 "故障码6";
CM_ SG_ 2265055088 S2A_AL_Fault_Page_48 "故障码页";
CM_ SG_ 2265055088 S2A_AL_Fault_Number1_48 "故障码1";
CM_ SG_ 2265055088 S2A_AL_Fault_Number2_48 "故障码2";
CM_ SG_ 2265055088 S2A_AL_Fault_Number3_48 "故障码3";
CM_ SG_ 2265055088 S2A_AL_Fault_Number4_48 "故障码4";
CM_ SG_ 2265055088 S2A_AL_Fault_Number5_48 "故障码5";
CM_ SG_ 2265055088 S2A_AL_Fault_Number6_48 "故障码6";
CM_ SG_ 2265055089 S2A_AL_Fault_Page_49 "故障码页";
CM_ SG_ 2265055089 S2A_AL_Fault_Number1_49 "故障码1";
CM_ SG_ 2265055089 S2A_AL_Fault_Number2_49 "故障码2";
CM_ SG_ 2265055089 S2A_AL_Fault_Number3_49 "故障码3";
CM_ SG_ 2265055089 S2A_AL_Fault_Number4_49 "故障码4";
CM_ SG_ 2265055089 S2A_AL_Fault_Number5_49 "故障码5";
CM_ SG_ 2265055089 S2A_AL_Fault_Number6_49 "故障码6";
CM_ SG_ 2265055090 S2A_AL_Fault_Page_50 "故障码页";
CM_ SG_ 2265055090 S2A_AL_Fault_Number1_50 "故障码1";
CM_ SG_ 2265055090 S2A_AL_Fault_Number2_50 "故障码2";
CM_ SG_ 2265055090 S2A_AL_Fault_Number3_50 "故障码3";
CM_ SG_ 2265055090 S2A_AL_Fault_Number4_50 "故障码4";
CM_ SG_ 2265055090 S2A_AL_Fault_Number5_50 "故障码5";
CM_ SG_ 2265055090 S2A_AL_Fault_Number6_50 "故障码6";
CM_ SG_ 2265055091 S2A_AL_Fault_Page_51 "故障码页";
CM_ SG_ 2265055091 S2A_AL_Fault_Number1_51 "故障码1";
CM_ SG_ 2265055091 S2A_AL_Fault_Number2_51 "故障码2";
CM_ SG_ 2265055091 S2A_AL_Fault_Number3_51 "故障码3";
CM_ SG_ 2265055091 S2A_AL_Fault_Number4_51 "故障码4";
CM_ SG_ 2265055091 S2A_AL_Fault_Number5_51 "故障码5";
CM_ SG_ 2265055091 S2A_AL_Fault_Number6_51 "故障码6";
CM_ SG_ 2265055092 S2A_AL_Fault_Page_52 "故障码页";
CM_ SG_ 2265055092 S2A_AL_Fault_Number1_52 "故障码1";
CM_ SG_ 2265055092 S2A_AL_Fault_Number2_52 "故障码2";
CM_ SG_ 2265055092 S2A_AL_Fault_Number3_52 "故障码3";
CM_ SG_ 2265055092 S2A_AL_Fault_Number4_52 "故障码4";
CM_ SG_ 2265055092 S2A_AL_Fault_Number5_52 "故障码5";
CM_ SG_ 2265055092 S2A_AL_Fault_Number6_52 "故障码6";
CM_ SG_ 2265055093 S2A_AL_Fault_Page_53 "故障码页";
CM_ SG_ 2265055093 S2A_AL_Fault_Number1_53 "故障码1";
CM_ SG_ 2265055093 S2A_AL_Fault_Number2_53 "故障码2";
CM_ SG_ 2265055093 S2A_AL_Fault_Number3_53 "故障码3";
CM_ SG_ 2265055093 S2A_AL_Fault_Number4_53 "故障码4";
CM_ SG_ 2265055093 S2A_AL_Fault_Number5_53 "故障码5";
CM_ SG_ 2265055093 S2A_AL_Fault_Number6_53 "故障码6";
CM_ SG_ 2265055094 S2A_AL_Fault_Page_54 "故障码页";
CM_ SG_ 2265055094 S2A_AL_Fault_Number1_54 "故障码1";
CM_ SG_ 2265055094 S2A_AL_Fault_Number2_54 "故障码2";
CM_ SG_ 2265055094 S2A_AL_Fault_Number3_54 "故障码3";
CM_ SG_ 2265055094 S2A_AL_Fault_Number4_54 "故障码4";
CM_ SG_ 2265055094 S2A_AL_Fault_Number5_54 "故障码5";
CM_ SG_ 2265055094 S2A_AL_Fault_Number6_54 "故障码6";
CM_ SG_ 2265055095 S2A_AL_Fault_Page_55 "故障码页";
CM_ SG_ 2265055095 S2A_AL_Fault_Number1_55 "故障码1";
CM_ SG_ 2265055095 S2A_AL_Fault_Number2_55 "故障码2";
CM_ SG_ 2265055095 S2A_AL_Fault_Number3_55 "故障码3";
CM_ SG_ 2265055095 S2A_AL_Fault_Number4_55 "故障码4";
CM_ SG_ 2265055095 S2A_AL_Fault_Number5_55 "故障码5";
CM_ SG_ 2265055095 S2A_AL_Fault_Number6_55 "故障码6";
CM_ SG_ 2265055096 S2A_AL_Fault_Page_56 "故障码页";
CM_ SG_ 2265055096 S2A_AL_Fault_Number1_56 "故障码1";
CM_ SG_ 2265055096 S2A_AL_Fault_Number2_56 "故障码2";
CM_ SG_ 2265055096 S2A_AL_Fault_Number3_56 "故障码3";
CM_ SG_ 2265055096 S2A_AL_Fault_Number4_56 "故障码4";
CM_ SG_ 2265055096 S2A_AL_Fault_Number5_56 "故障码5";
CM_ SG_ 2265055096 S2A_AL_Fault_Number6_56 "故障码6";
CM_ SG_ 2265055097 S2A_AL_Fault_Page_57 "故障码页";
CM_ SG_ 2265055097 S2A_AL_Fault_Number1_57 "故障码1";
CM_ SG_ 2265055097 S2A_AL_Fault_Number2_57 "故障码2";
CM_ SG_ 2265055097 S2A_AL_Fault_Number3_57 "故障码3";
CM_ SG_ 2265055097 S2A_AL_Fault_Number4_57 "故障码4";
CM_ SG_ 2265055097 S2A_AL_Fault_Number5_57 "故障码5";
CM_ SG_ 2265055097 S2A_AL_Fault_Number6_57 "故障码6";
CM_ SG_ 2265055098 S2A_AL_Fault_Page_58 "故障码页";
CM_ SG_ 2265055098 S2A_AL_Fault_Number1_58 "故障码1";
CM_ SG_ 2265055098 S2A_AL_Fault_Number2_58 "故障码2";
CM_ SG_ 2265055098 S2A_AL_Fault_Number3_58 "故障码3";
CM_ SG_ 2265055098 S2A_AL_Fault_Number4_58 "故障码4";
CM_ SG_ 2265055098 S2A_AL_Fault_Number5_58 "故障码5";
CM_ SG_ 2265055098 S2A_AL_Fault_Number6_58 "故障码6";
CM_ SG_ 2265055099 S2A_AL_Fault_Page_59 "故障码页";
CM_ SG_ 2265055099 S2A_AL_Fault_Number1_59 "故障码1";
CM_ SG_ 2265055099 S2A_AL_Fault_Number2_59 "故障码2";
CM_ SG_ 2265055099 S2A_AL_Fault_Number3_59 "故障码3";
CM_ SG_ 2265055099 S2A_AL_Fault_Number4_59 "故障码4";
CM_ SG_ 2265055099 S2A_AL_Fault_Number5_59 "故障码5";
CM_ SG_ 2265055099 S2A_AL_Fault_Number6_59 "故障码6";
CM_ SG_ 2265055100 S2A_AL_Fault_Page_60 "故障码页";
CM_ SG_ 2265055100 S2A_AL_Fault_Number1_60 "故障码1";
CM_ SG_ 2265055100 S2A_AL_Fault_Number2_60 "故障码2";
CM_ SG_ 2265055100 S2A_AL_Fault_Number3_60 "故障码3";
CM_ SG_ 2265055100 S2A_AL_Fault_Number4_60 "故障码4";
CM_ SG_ 2265055100 S2A_AL_Fault_Number5_60 "故障码5";
CM_ SG_ 2265055100 S2A_AL_Fault_Number6_60 "故障码6";
CM_ SG_ 2265055101 S2A_AL_Fault_Page_61 "故障码页";
CM_ SG_ 2265055101 S2A_AL_Fault_Number1_61 "故障码1";
CM_ SG_ 2265055101 S2A_AL_Fault_Number2_61 "故障码2";
CM_ SG_ 2265055101 S2A_AL_Fault_Number3_61 "故障码3";
CM_ SG_ 2265055101 S2A_AL_Fault_Number4_61 "故障码4";
CM_ SG_ 2265055101 S2A_AL_Fault_Number5_61 "故障码5";
CM_ SG_ 2265055101 S2A_AL_Fault_Number6_61 "故障码6";
CM_ SG_ 2265055102 S2A_AL_Fault_Page_62 "故障码页";
CM_ SG_ 2265055102 S2A_AL_Fault_Number1_62 "故障码1";
CM_ SG_ 2265055102 S2A_AL_Fault_Number2_62 "故障码2";
CM_ SG_ 2265055102 S2A_AL_Fault_Number3_62 "故障码3";
CM_ SG_ 2265055102 S2A_AL_Fault_Number4_62 "故障码4";
CM_ SG_ 2265055102 S2A_AL_Fault_Number5_62 "故障码5";
CM_ SG_ 2265055102 S2A_AL_Fault_Number6_62 "故障码6";
CM_ SG_ 2265055103 S2A_AL_Fault_Page_63 "故障码页";
CM_ SG_ 2265055103 S2A_AL_Fault_Number1_63 "故障码1";
CM_ SG_ 2265055103 S2A_AL_Fault_Number2_63 "故障码2";
CM_ SG_ 2265055103 S2A_AL_Fault_Number3_63 "故障码3";
CM_ SG_ 2265055103 S2A_AL_Fault_Number4_63 "故障码4";
CM_ SG_ 2265055103 S2A_AL_Fault_Number5_63 "故障码5";
CM_ SG_ 2265055103 S2A_AL_Fault_Number6_63 "故障码6";
CM_ SG_ 2332163905 CRC_S2A_S1_01 "S2A概要数据1 的CRC（未实现校验）";
CM_ SG_ 2332163905 BAT_U_HVS_01 "电柜外侧高压采样";
CM_ SG_ 2332163905 BAT_U_TOT_HVS_01 "电柜所有电芯电压累积和";
CM_ SG_ 2332163905 HIS_NumofChg_DisChgCycles_01 "历史累积充放电循环次数";
CM_ SG_ 2332163905 BAT_standingstatus_01 "静置状态标志位";
CM_ SG_ 2332163906 CRC_S2A_S1_02 "S2A概要数据1 的CRC（未实现校验）";
CM_ SG_ 2332163906 BAT_U_HVS_02 "电柜外侧高压采样";
CM_ SG_ 2332163906 BAT_U_TOT_HVS_02 "电柜所有电芯电压累积和";
CM_ SG_ 2332163906 HIS_NumofChg_DisChgCycles_02 "历史累积充放电循环次数";
CM_ SG_ 2332163906 BAT_standingstatus_02 "静置状态标志位";
CM_ SG_ 2332163907 CRC_S2A_S1_03 "S2A概要数据1 的CRC（未实现校验）";
CM_ SG_ 2332163907 BAT_U_HVS_03 "电柜外侧高压采样";
CM_ SG_ 2332163907 BAT_U_TOT_HVS_03 "电柜所有电芯电压累积和";
CM_ SG_ 2332163907 HIS_NumofChg_DisChgCycles_03 "历史累积充放电循环次数";
CM_ SG_ 2332163907 BAT_standingstatus_03 "静置状态标志位";
CM_ SG_ 2332163908 CRC_S2A_S1_04 "S2A概要数据1 的CRC（未实现校验）";
CM_ SG_ 2332163908 BAT_U_HVS_04 "电柜外侧高压采样";
CM_ SG_ 2332163908 BAT_U_TOT_HVS_04 "电柜所有电芯电压累积和";
CM_ SG_ 2332163908 HIS_NumofChg_DisChgCycles_04 "历史累积充放电循环次数";
CM_ SG_ 2332163908 BAT_standingstatus_04 "静置状态标志位";
CM_ SG_ 2332163909 CRC_S2A_S1_05 "S2A概要数据1 的CRC（未实现校验）";
CM_ SG_ 2332163909 BAT_U_HVS_05 "电柜外侧高压采样";
CM_ SG_ 2332163909 BAT_U_TOT_HVS_05 "电柜所有电芯电压累积和";
CM_ SG_ 2332163909 HIS_NumofChg_DisChgCycles_05 "历史累积充放电循环次数";
CM_ SG_ 2332163909 BAT_standingstatus_05 "静置状态标志位";
CM_ SG_ 2332163910 CRC_S2A_S1_06 "S2A概要数据1 的CRC（未实现校验）";
CM_ SG_ 2332163910 BAT_U_HVS_06 "电柜外侧高压采样";
CM_ SG_ 2332163910 BAT_U_TOT_HVS_06 "电柜所有电芯电压累积和";
CM_ SG_ 2332163910 HIS_NumofChg_DisChgCycles_06 "历史累积充放电循环次数";
CM_ SG_ 2332163910 BAT_standingstatus_06 "静置状态标志位";
CM_ SG_ 2332163911 CRC_S2A_S1_07 "S2A概要数据1 的CRC（未实现校验）";
CM_ SG_ 2332163911 BAT_U_HVS_07 "电柜外侧高压采样";
CM_ SG_ 2332163911 BAT_U_TOT_HVS_07 "电柜所有电芯电压累积和";
CM_ SG_ 2332163911 HIS_NumofChg_DisChgCycles_07 "历史累积充放电循环次数";
CM_ SG_ 2332163911 BAT_standingstatus_07 "静置状态标志位";
CM_ SG_ 2332163912 CRC_S2A_S1_08 "S2A概要数据1 的CRC（未实现校验）";
CM_ SG_ 2332163912 BAT_U_HVS_08 "电柜外侧高压采样";
CM_ SG_ 2332163912 BAT_U_TOT_HVS_08 "电柜所有电芯电压累积和";
CM_ SG_ 2332163912 HIS_NumofChg_DisChgCycles_08 "历史累积充放电循环次数";
CM_ SG_ 2332163912 BAT_standingstatus_08 "静置状态标志位";
CM_ SG_ 2332163913 CRC_S2A_S1_09 "S2A概要数据1 的CRC（未实现校验）";
CM_ SG_ 2332163913 BAT_U_HVS_09 "电柜外侧高压采样";
CM_ SG_ 2332163913 BAT_U_TOT_HVS_09 "电柜所有电芯电压累积和";
CM_ SG_ 2332163913 HIS_NumofChg_DisChgCycles_09 "历史累积充放电循环次数";
CM_ SG_ 2332163913 BAT_standingstatus_09 "静置状态标志位";
CM_ SG_ 2332163914 CRC_S2A_S1_10 "S2A概要数据1 的CRC（未实现校验）";
CM_ SG_ 2332163914 BAT_U_HVS_10 "电柜外侧高压采样";
CM_ SG_ 2332163914 BAT_U_TOT_HVS_10 "电柜所有电芯电压累积和";
CM_ SG_ 2332163914 HIS_NumofChg_DisChgCycles_10 "历史累积充放电循环次数";
CM_ SG_ 2332163914 BAT_standingstatus_10 "静置状态标志位";
CM_ SG_ 2332163915 CRC_S2A_S1_11 "S2A概要数据1 的CRC（未实现校验）";
CM_ SG_ 2332163915 BAT_U_HVS_11 "电柜外侧高压采样";
CM_ SG_ 2332163915 BAT_U_TOT_HVS_11 "电柜所有电芯电压累积和";
CM_ SG_ 2332163915 HIS_NumofChg_DisChgCycles_11 "历史累积充放电循环次数";
CM_ SG_ 2332163915 BAT_standingstatus_11 "静置状态标志位";
CM_ SG_ 2332163916 CRC_S2A_S1_12 "S2A概要数据1 的CRC（未实现校验）";
CM_ SG_ 2332163916 BAT_U_HVS_12 "电柜外侧高压采样";
CM_ SG_ 2332163916 BAT_U_TOT_HVS_12 "电柜所有电芯电压累积和";
CM_ SG_ 2332163916 HIS_NumofChg_DisChgCycles_12 "历史累积充放电循环次数";
CM_ SG_ 2332163916 BAT_standingstatus_12 "静置状态标志位";
CM_ SG_ 2332163917 CRC_S2A_S1_13 "S2A概要数据1 的CRC（未实现校验）";
CM_ SG_ 2332163917 BAT_U_HVS_13 "电柜外侧高压采样";
CM_ SG_ 2332163917 BAT_U_TOT_HVS_13 "电柜所有电芯电压累积和";
CM_ SG_ 2332163917 HIS_NumofChg_DisChgCycles_13 "历史累积充放电循环次数";
CM_ SG_ 2332163917 BAT_standingstatus_13 "静置状态标志位";
CM_ SG_ 2332163918 CRC_S2A_S1_14 "S2A概要数据1 的CRC（未实现校验）";
CM_ SG_ 2332163918 BAT_U_HVS_14 "电柜外侧高压采样";
CM_ SG_ 2332163918 BAT_U_TOT_HVS_14 "电柜所有电芯电压累积和";
CM_ SG_ 2332163918 HIS_NumofChg_DisChgCycles_14 "历史累积充放电循环次数";
CM_ SG_ 2332163918 BAT_standingstatus_14 "静置状态标志位";
CM_ SG_ 2332163919 CRC_S2A_S1_15 "S2A概要数据1 的CRC（未实现校验）";
CM_ SG_ 2332163919 BAT_U_HVS_15 "电柜外侧高压采样";
CM_ SG_ 2332163919 BAT_U_TOT_HVS_15 "电柜所有电芯电压累积和";
CM_ SG_ 2332163919 HIS_NumofChg_DisChgCycles_15 "历史累积充放电循环次数";
CM_ SG_ 2332163919 BAT_standingstatus_15 "静置状态标志位";
CM_ SG_ 2332163920 CRC_S2A_S1_16 "S2A概要数据1 的CRC（未实现校验）";
CM_ SG_ 2332163920 BAT_U_HVS_16 "电柜外侧高压采样";
CM_ SG_ 2332163920 BAT_U_TOT_HVS_16 "电柜所有电芯电压累积和";
CM_ SG_ 2332163920 HIS_NumofChg_DisChgCycles_16 "历史累积充放电循环次数";
CM_ SG_ 2332163920 BAT_standingstatus_16 "静置状态标志位";
CM_ SG_ 2332163921 CRC_S2A_S1_17 "S2A概要数据1 的CRC（未实现校验）";
CM_ SG_ 2332163921 BAT_U_HVS_17 "电柜外侧高压采样";
CM_ SG_ 2332163921 BAT_U_TOT_HVS_17 "电柜所有电芯电压累积和";
CM_ SG_ 2332163921 HIS_NumofChg_DisChgCycles_17 "历史累积充放电循环次数";
CM_ SG_ 2332163921 BAT_standingstatus_17 "静置状态标志位";
CM_ SG_ 2332163922 CRC_S2A_S1_18 "S2A概要数据1 的CRC（未实现校验）";
CM_ SG_ 2332163922 BAT_U_HVS_18 "电柜外侧高压采样";
CM_ SG_ 2332163922 BAT_U_TOT_HVS_18 "电柜所有电芯电压累积和";
CM_ SG_ 2332163922 HIS_NumofChg_DisChgCycles_18 "历史累积充放电循环次数";
CM_ SG_ 2332163922 BAT_standingstatus_18 "静置状态标志位";
CM_ SG_ 2332163923 CRC_S2A_S1_19 "S2A概要数据1 的CRC（未实现校验）";
CM_ SG_ 2332163923 BAT_U_HVS_19 "电柜外侧高压采样";
CM_ SG_ 2332163923 BAT_U_TOT_HVS_19 "电柜所有电芯电压累积和";
CM_ SG_ 2332163923 HIS_NumofChg_DisChgCycles_19 "历史累积充放电循环次数";
CM_ SG_ 2332163923 BAT_standingstatus_19 "静置状态标志位";
CM_ SG_ 2332163924 CRC_S2A_S1_20 "S2A概要数据1 的CRC（未实现校验）";
CM_ SG_ 2332163924 BAT_U_HVS_20 "电柜外侧高压采样";
CM_ SG_ 2332163924 BAT_U_TOT_HVS_20 "电柜所有电芯电压累积和";
CM_ SG_ 2332163924 HIS_NumofChg_DisChgCycles_20 "历史累积充放电循环次数";
CM_ SG_ 2332163924 BAT_standingstatus_20 "静置状态标志位";
CM_ SG_ 2332163925 CRC_S2A_S1_21 "S2A概要数据1 的CRC（未实现校验）";
CM_ SG_ 2332163925 BAT_U_HVS_21 "电柜外侧高压采样";
CM_ SG_ 2332163925 BAT_U_TOT_HVS_21 "电柜所有电芯电压累积和";
CM_ SG_ 2332163925 HIS_NumofChg_DisChgCycles_21 "历史累积充放电循环次数";
CM_ SG_ 2332163925 BAT_standingstatus_21 "静置状态标志位";
CM_ SG_ 2332163926 CRC_S2A_S1_22 "S2A概要数据1 的CRC（未实现校验）";
CM_ SG_ 2332163926 BAT_U_HVS_22 "电柜外侧高压采样";
CM_ SG_ 2332163926 BAT_U_TOT_HVS_22 "电柜所有电芯电压累积和";
CM_ SG_ 2332163926 HIS_NumofChg_DisChgCycles_22 "历史累积充放电循环次数";
CM_ SG_ 2332163926 BAT_standingstatus_22 "静置状态标志位";
CM_ SG_ 2332163927 CRC_S2A_S1_23 "S2A概要数据1 的CRC（未实现校验）";
CM_ SG_ 2332163927 BAT_U_HVS_23 "电柜外侧高压采样";
CM_ SG_ 2332163927 BAT_U_TOT_HVS_23 "电柜所有电芯电压累积和";
CM_ SG_ 2332163927 HIS_NumofChg_DisChgCycles_23 "历史累积充放电循环次数";
CM_ SG_ 2332163927 BAT_standingstatus_23 "静置状态标志位";
CM_ SG_ 2332163928 CRC_S2A_S1_24 "S2A概要数据1 的CRC（未实现校验）";
CM_ SG_ 2332163928 BAT_U_HVS_24 "电柜外侧高压采样";
CM_ SG_ 2332163928 BAT_U_TOT_HVS_24 "电柜所有电芯电压累积和";
CM_ SG_ 2332163928 HIS_NumofChg_DisChgCycles_24 "历史累积充放电循环次数";
CM_ SG_ 2332163928 BAT_standingstatus_24 "静置状态标志位";
CM_ SG_ 2332163929 CRC_S2A_S1_25 "S2A概要数据1 的CRC（未实现校验）";
CM_ SG_ 2332163929 BAT_U_HVS_25 "电柜外侧高压采样";
CM_ SG_ 2332163929 BAT_U_TOT_HVS_25 "电柜所有电芯电压累积和";
CM_ SG_ 2332163929 HIS_NumofChg_DisChgCycles_25 "历史累积充放电循环次数";
CM_ SG_ 2332163929 BAT_standingstatus_25 "静置状态标志位";
CM_ SG_ 2332163930 CRC_S2A_S1_26 "S2A概要数据1 的CRC（未实现校验）";
CM_ SG_ 2332163930 BAT_U_HVS_26 "电柜外侧高压采样";
CM_ SG_ 2332163930 BAT_U_TOT_HVS_26 "电柜所有电芯电压累积和";
CM_ SG_ 2332163930 HIS_NumofChg_DisChgCycles_26 "历史累积充放电循环次数";
CM_ SG_ 2332163930 BAT_standingstatus_26 "静置状态标志位";
CM_ SG_ 2332163931 CRC_S2A_S1_27 "S2A概要数据1 的CRC（未实现校验）";
CM_ SG_ 2332163931 BAT_U_HVS_27 "电柜外侧高压采样";
CM_ SG_ 2332163931 BAT_U_TOT_HVS_27 "电柜所有电芯电压累积和";
CM_ SG_ 2332163931 HIS_NumofChg_DisChgCycles_27 "历史累积充放电循环次数";
CM_ SG_ 2332163931 BAT_standingstatus_27 "静置状态标志位";
CM_ SG_ 2332163932 CRC_S2A_S1_28 "S2A概要数据1 的CRC（未实现校验）";
CM_ SG_ 2332163932 BAT_U_HVS_28 "电柜外侧高压采样";
CM_ SG_ 2332163932 BAT_U_TOT_HVS_28 "电柜所有电芯电压累积和";
CM_ SG_ 2332163932 HIS_NumofChg_DisChgCycles_28 "历史累积充放电循环次数";
CM_ SG_ 2332163932 BAT_standingstatus_28 "静置状态标志位";
CM_ SG_ 2332163933 CRC_S2A_S1_29 "S2A概要数据1 的CRC（未实现校验）";
CM_ SG_ 2332163933 BAT_U_HVS_29 "电柜外侧高压采样";
CM_ SG_ 2332163933 BAT_U_TOT_HVS_29 "电柜所有电芯电压累积和";
CM_ SG_ 2332163933 HIS_NumofChg_DisChgCycles_29 "历史累积充放电循环次数";
CM_ SG_ 2332163933 BAT_standingstatus_29 "静置状态标志位";
CM_ SG_ 2332163934 CRC_S2A_S1_30 "S2A概要数据1 的CRC（未实现校验）";
CM_ SG_ 2332163934 BAT_U_HVS_30 "电柜外侧高压采样";
CM_ SG_ 2332163934 BAT_U_TOT_HVS_30 "电柜所有电芯电压累积和";
CM_ SG_ 2332163934 HIS_NumofChg_DisChgCycles_30 "历史累积充放电循环次数";
CM_ SG_ 2332163934 BAT_standingstatus_30 "静置状态标志位";
CM_ SG_ 2332163935 CRC_S2A_S1_31 "S2A概要数据1 的CRC（未实现校验）";
CM_ SG_ 2332163935 BAT_U_HVS_31 "电柜外侧高压采样";
CM_ SG_ 2332163935 BAT_U_TOT_HVS_31 "电柜所有电芯电压累积和";
CM_ SG_ 2332163935 HIS_NumofChg_DisChgCycles_31 "历史累积充放电循环次数";
CM_ SG_ 2332163935 BAT_standingstatus_31 "静置状态标志位";
CM_ SG_ 2332163936 CRC_S2A_S1_32 "S2A概要数据1 的CRC（未实现校验）";
CM_ SG_ 2332163936 BAT_U_HVS_32 "电柜外侧高压采样";
CM_ SG_ 2332163936 BAT_U_TOT_HVS_32 "电柜所有电芯电压累积和";
CM_ SG_ 2332163936 HIS_NumofChg_DisChgCycles_32 "历史累积充放电循环次数";
CM_ SG_ 2332163936 BAT_standingstatus_32 "静置状态标志位";
CM_ SG_ 2332163937 CRC_S2A_S1_33 "S2A概要数据1 的CRC（未实现校验）";
CM_ SG_ 2332163937 BAT_U_HVS_33 "电柜外侧高压采样";
CM_ SG_ 2332163937 BAT_U_TOT_HVS_33 "电柜所有电芯电压累积和";
CM_ SG_ 2332163937 HIS_NumofChg_DisChgCycles_33 "历史累积充放电循环次数";
CM_ SG_ 2332163937 BAT_standingstatus_33 "静置状态标志位";
CM_ SG_ 2332163938 CRC_S2A_S1_34 "S2A概要数据1 的CRC（未实现校验）";
CM_ SG_ 2332163938 BAT_U_HVS_34 "电柜外侧高压采样";
CM_ SG_ 2332163938 BAT_U_TOT_HVS_34 "电柜所有电芯电压累积和";
CM_ SG_ 2332163938 HIS_NumofChg_DisChgCycles_34 "历史累积充放电循环次数";
CM_ SG_ 2332163938 BAT_standingstatus_34 "静置状态标志位";
CM_ SG_ 2332163939 CRC_S2A_S1_35 "S2A概要数据1 的CRC（未实现校验）";
CM_ SG_ 2332163939 BAT_U_HVS_35 "电柜外侧高压采样";
CM_ SG_ 2332163939 BAT_U_TOT_HVS_35 "电柜所有电芯电压累积和";
CM_ SG_ 2332163939 HIS_NumofChg_DisChgCycles_35 "历史累积充放电循环次数";
CM_ SG_ 2332163939 BAT_standingstatus_35 "静置状态标志位";
CM_ SG_ 2332163940 CRC_S2A_S1_36 "S2A概要数据1 的CRC（未实现校验）";
CM_ SG_ 2332163940 BAT_U_HVS_36 "电柜外侧高压采样";
CM_ SG_ 2332163940 BAT_U_TOT_HVS_36 "电柜所有电芯电压累积和";
CM_ SG_ 2332163940 HIS_NumofChg_DisChgCycles_36 "历史累积充放电循环次数";
CM_ SG_ 2332163940 BAT_standingstatus_36 "静置状态标志位";
CM_ SG_ 2332163941 CRC_S2A_S1_37 "S2A概要数据1 的CRC（未实现校验）";
CM_ SG_ 2332163941 BAT_U_HVS_37 "电柜外侧高压采样";
CM_ SG_ 2332163941 BAT_U_TOT_HVS_37 "电柜所有电芯电压累积和";
CM_ SG_ 2332163941 HIS_NumofChg_DisChgCycles_37 "历史累积充放电循环次数";
CM_ SG_ 2332163941 BAT_standingstatus_37 "静置状态标志位";
CM_ SG_ 2332163942 CRC_S2A_S1_38 "S2A概要数据1 的CRC（未实现校验）";
CM_ SG_ 2332163942 BAT_U_HVS_38 "电柜外侧高压采样";
CM_ SG_ 2332163942 BAT_U_TOT_HVS_38 "电柜所有电芯电压累积和";
CM_ SG_ 2332163942 HIS_NumofChg_DisChgCycles_38 "历史累积充放电循环次数";
CM_ SG_ 2332163942 BAT_standingstatus_38 "静置状态标志位";
CM_ SG_ 2332163943 CRC_S2A_S1_39 "S2A概要数据1 的CRC（未实现校验）";
CM_ SG_ 2332163943 BAT_U_HVS_39 "电柜外侧高压采样";
CM_ SG_ 2332163943 BAT_U_TOT_HVS_39 "电柜所有电芯电压累积和";
CM_ SG_ 2332163943 HIS_NumofChg_DisChgCycles_39 "历史累积充放电循环次数";
CM_ SG_ 2332163943 BAT_standingstatus_39 "静置状态标志位";
CM_ SG_ 2332163944 CRC_S2A_S1_40 "S2A概要数据1 的CRC（未实现校验）";
CM_ SG_ 2332163944 BAT_U_HVS_40 "电柜外侧高压采样";
CM_ SG_ 2332163944 BAT_U_TOT_HVS_40 "电柜所有电芯电压累积和";
CM_ SG_ 2332163944 HIS_NumofChg_DisChgCycles_40 "历史累积充放电循环次数";
CM_ SG_ 2332163944 BAT_standingstatus_40 "静置状态标志位";
CM_ SG_ 2332163945 CRC_S2A_S1_41 "S2A概要数据1 的CRC（未实现校验）";
CM_ SG_ 2332163945 BAT_U_HVS_41 "电柜外侧高压采样";
CM_ SG_ 2332163945 BAT_U_TOT_HVS_41 "电柜所有电芯电压累积和";
CM_ SG_ 2332163945 HIS_NumofChg_DisChgCycles_41 "历史累积充放电循环次数";
CM_ SG_ 2332163945 BAT_standingstatus_41 "静置状态标志位";
CM_ SG_ 2332163946 CRC_S2A_S1_42 "S2A概要数据1 的CRC（未实现校验）";
CM_ SG_ 2332163946 BAT_U_HVS_42 "电柜外侧高压采样";
CM_ SG_ 2332163946 BAT_U_TOT_HVS_42 "电柜所有电芯电压累积和";
CM_ SG_ 2332163946 HIS_NumofChg_DisChgCycles_42 "历史累积充放电循环次数";
CM_ SG_ 2332163946 BAT_standingstatus_42 "静置状态标志位";
CM_ SG_ 2332163947 CRC_S2A_S1_43 "S2A概要数据1 的CRC（未实现校验）";
CM_ SG_ 2332163947 BAT_U_HVS_43 "电柜外侧高压采样";
CM_ SG_ 2332163947 BAT_U_TOT_HVS_43 "电柜所有电芯电压累积和";
CM_ SG_ 2332163947 HIS_NumofChg_DisChgCycles_43 "历史累积充放电循环次数";
CM_ SG_ 2332163947 BAT_standingstatus_43 "静置状态标志位";
CM_ SG_ 2332163948 CRC_S2A_S1_44 "S2A概要数据1 的CRC（未实现校验）";
CM_ SG_ 2332163948 BAT_U_HVS_44 "电柜外侧高压采样";
CM_ SG_ 2332163948 BAT_U_TOT_HVS_44 "电柜所有电芯电压累积和";
CM_ SG_ 2332163948 HIS_NumofChg_DisChgCycles_44 "历史累积充放电循环次数";
CM_ SG_ 2332163948 BAT_standingstatus_44 "静置状态标志位";
CM_ SG_ 2332163949 CRC_S2A_S1_45 "S2A概要数据1 的CRC（未实现校验）";
CM_ SG_ 2332163949 BAT_U_HVS_45 "电柜外侧高压采样";
CM_ SG_ 2332163949 BAT_U_TOT_HVS_45 "电柜所有电芯电压累积和";
CM_ SG_ 2332163949 HIS_NumofChg_DisChgCycles_45 "历史累积充放电循环次数";
CM_ SG_ 2332163949 BAT_standingstatus_45 "静置状态标志位";
CM_ SG_ 2332163950 CRC_S2A_S1_46 "S2A概要数据1 的CRC（未实现校验）";
CM_ SG_ 2332163950 BAT_U_HVS_46 "电柜外侧高压采样";
CM_ SG_ 2332163950 BAT_U_TOT_HVS_46 "电柜所有电芯电压累积和";
CM_ SG_ 2332163950 HIS_NumofChg_DisChgCycles_46 "历史累积充放电循环次数";
CM_ SG_ 2332163950 BAT_standingstatus_46 "静置状态标志位";
CM_ SG_ 2332163951 CRC_S2A_S1_47 "S2A概要数据1 的CRC（未实现校验）";
CM_ SG_ 2332163951 BAT_U_HVS_47 "电柜外侧高压采样";
CM_ SG_ 2332163951 BAT_U_TOT_HVS_47 "电柜所有电芯电压累积和";
CM_ SG_ 2332163951 HIS_NumofChg_DisChgCycles_47 "历史累积充放电循环次数";
CM_ SG_ 2332163951 BAT_standingstatus_47 "静置状态标志位";
CM_ SG_ 2332163952 CRC_S2A_S1_48 "S2A概要数据1 的CRC（未实现校验）";
CM_ SG_ 2332163952 BAT_U_HVS_48 "电柜外侧高压采样";
CM_ SG_ 2332163952 BAT_U_TOT_HVS_48 "电柜所有电芯电压累积和";
CM_ SG_ 2332163952 HIS_NumofChg_DisChgCycles_48 "历史累积充放电循环次数";
CM_ SG_ 2332163952 BAT_standingstatus_48 "静置状态标志位";
CM_ SG_ 2332163953 CRC_S2A_S1_49 "S2A概要数据1 的CRC（未实现校验）";
CM_ SG_ 2332163953 BAT_U_HVS_49 "电柜外侧高压采样";
CM_ SG_ 2332163953 BAT_U_TOT_HVS_49 "电柜所有电芯电压累积和";
CM_ SG_ 2332163953 HIS_NumofChg_DisChgCycles_49 "历史累积充放电循环次数";
CM_ SG_ 2332163953 BAT_standingstatus_49 "静置状态标志位";
CM_ SG_ 2332163954 CRC_S2A_S1_50 "S2A概要数据1 的CRC（未实现校验）";
CM_ SG_ 2332163954 BAT_U_HVS_50 "电柜外侧高压采样";
CM_ SG_ 2332163954 BAT_U_TOT_HVS_50 "电柜所有电芯电压累积和";
CM_ SG_ 2332163954 HIS_NumofChg_DisChgCycles_50 "历史累积充放电循环次数";
CM_ SG_ 2332163954 BAT_standingstatus_50 "静置状态标志位";
CM_ SG_ 2332163955 CRC_S2A_S1_51 "S2A概要数据1 的CRC（未实现校验）";
CM_ SG_ 2332163955 BAT_U_HVS_51 "电柜外侧高压采样";
CM_ SG_ 2332163955 BAT_U_TOT_HVS_51 "电柜所有电芯电压累积和";
CM_ SG_ 2332163955 HIS_NumofChg_DisChgCycles_51 "历史累积充放电循环次数";
CM_ SG_ 2332163955 BAT_standingstatus_51 "静置状态标志位";
CM_ SG_ 2332163956 CRC_S2A_S1_52 "S2A概要数据1 的CRC（未实现校验）";
CM_ SG_ 2332163956 BAT_U_HVS_52 "电柜外侧高压采样";
CM_ SG_ 2332163956 BAT_U_TOT_HVS_52 "电柜所有电芯电压累积和";
CM_ SG_ 2332163956 HIS_NumofChg_DisChgCycles_52 "历史累积充放电循环次数";
CM_ SG_ 2332163956 BAT_standingstatus_52 "静置状态标志位";
CM_ SG_ 2332163957 CRC_S2A_S1_53 "S2A概要数据1 的CRC（未实现校验）";
CM_ SG_ 2332163957 BAT_U_HVS_53 "电柜外侧高压采样";
CM_ SG_ 2332163957 BAT_U_TOT_HVS_53 "电柜所有电芯电压累积和";
CM_ SG_ 2332163957 HIS_NumofChg_DisChgCycles_53 "历史累积充放电循环次数";
CM_ SG_ 2332163957 BAT_standingstatus_53 "静置状态标志位";
CM_ SG_ 2332163958 CRC_S2A_S1_54 "S2A概要数据1 的CRC（未实现校验）";
CM_ SG_ 2332163958 BAT_U_HVS_54 "电柜外侧高压采样";
CM_ SG_ 2332163958 BAT_U_TOT_HVS_54 "电柜所有电芯电压累积和";
CM_ SG_ 2332163958 HIS_NumofChg_DisChgCycles_54 "历史累积充放电循环次数";
CM_ SG_ 2332163958 BAT_standingstatus_54 "静置状态标志位";
CM_ SG_ 2332163959 CRC_S2A_S1_55 "S2A概要数据1 的CRC（未实现校验）";
CM_ SG_ 2332163959 BAT_U_HVS_55 "电柜外侧高压采样";
CM_ SG_ 2332163959 BAT_U_TOT_HVS_55 "电柜所有电芯电压累积和";
CM_ SG_ 2332163959 HIS_NumofChg_DisChgCycles_55 "历史累积充放电循环次数";
CM_ SG_ 2332163959 BAT_standingstatus_55 "静置状态标志位";
CM_ SG_ 2332163960 CRC_S2A_S1_56 "S2A概要数据1 的CRC（未实现校验）";
CM_ SG_ 2332163960 BAT_U_HVS_56 "电柜外侧高压采样";
CM_ SG_ 2332163960 BAT_U_TOT_HVS_56 "电柜所有电芯电压累积和";
CM_ SG_ 2332163960 HIS_NumofChg_DisChgCycles_56 "历史累积充放电循环次数";
CM_ SG_ 2332163960 BAT_standingstatus_56 "静置状态标志位";
CM_ SG_ 2332163961 CRC_S2A_S1_57 "S2A概要数据1 的CRC（未实现校验）";
CM_ SG_ 2332163961 BAT_U_HVS_57 "电柜外侧高压采样";
CM_ SG_ 2332163961 BAT_U_TOT_HVS_57 "电柜所有电芯电压累积和";
CM_ SG_ 2332163961 HIS_NumofChg_DisChgCycles_57 "历史累积充放电循环次数";
CM_ SG_ 2332163961 BAT_standingstatus_57 "静置状态标志位";
CM_ SG_ 2332163962 CRC_S2A_S1_58 "S2A概要数据1 的CRC（未实现校验）";
CM_ SG_ 2332163962 BAT_U_HVS_58 "电柜外侧高压采样";
CM_ SG_ 2332163962 BAT_U_TOT_HVS_58 "电柜所有电芯电压累积和";
CM_ SG_ 2332163962 HIS_NumofChg_DisChgCycles_58 "历史累积充放电循环次数";
CM_ SG_ 2332163962 BAT_standingstatus_58 "静置状态标志位";
CM_ SG_ 2332163963 CRC_S2A_S1_59 "S2A概要数据1 的CRC（未实现校验）";
CM_ SG_ 2332163963 BAT_U_HVS_59 "电柜外侧高压采样";
CM_ SG_ 2332163963 BAT_U_TOT_HVS_59 "电柜所有电芯电压累积和";
CM_ SG_ 2332163963 HIS_NumofChg_DisChgCycles_59 "历史累积充放电循环次数";
CM_ SG_ 2332163963 BAT_standingstatus_59 "静置状态标志位";
CM_ SG_ 2332163964 CRC_S2A_S1_60 "S2A概要数据1 的CRC（未实现校验）";
CM_ SG_ 2332163964 BAT_U_HVS_60 "电柜外侧高压采样";
CM_ SG_ 2332163964 BAT_U_TOT_HVS_60 "电柜所有电芯电压累积和";
CM_ SG_ 2332163964 HIS_NumofChg_DisChgCycles_60 "历史累积充放电循环次数";
CM_ SG_ 2332163964 BAT_standingstatus_60 "静置状态标志位";
CM_ SG_ 2332163965 CRC_S2A_S1_61 "S2A概要数据1 的CRC（未实现校验）";
CM_ SG_ 2332163965 BAT_U_HVS_61 "电柜外侧高压采样";
CM_ SG_ 2332163965 BAT_U_TOT_HVS_61 "电柜所有电芯电压累积和";
CM_ SG_ 2332163965 HIS_NumofChg_DisChgCycles_61 "历史累积充放电循环次数";
CM_ SG_ 2332163965 BAT_standingstatus_61 "静置状态标志位";
CM_ SG_ 2332163966 CRC_S2A_S1_62 "S2A概要数据1 的CRC（未实现校验）";
CM_ SG_ 2332163966 BAT_U_HVS_62 "电柜外侧高压采样";
CM_ SG_ 2332163966 BAT_U_TOT_HVS_62 "电柜所有电芯电压累积和";
CM_ SG_ 2332163966 HIS_NumofChg_DisChgCycles_62 "历史累积充放电循环次数";
CM_ SG_ 2332163966 BAT_standingstatus_62 "静置状态标志位";
CM_ SG_ 2332163967 CRC_S2A_S1_63 "S2A概要数据1 的CRC（未实现校验）";
CM_ SG_ 2332163967 BAT_U_HVS_63 "电柜外侧高压采样";
CM_ SG_ 2332163967 BAT_U_TOT_HVS_63 "电柜所有电芯电压累积和";
CM_ SG_ 2332163967 HIS_NumofChg_DisChgCycles_63 "历史累积充放电循环次数";
CM_ SG_ 2332163967 BAT_standingstatus_63 "静置状态标志位";
CM_ SG_ 2332229441 CRC_S2A_S2_01 "S2A概要数据2 的CRC";
CM_ SG_ 2332229441 ALIV_ST_SW_HVS_01 "生命信号，0~15循环";
CM_ SG_ 2332229441 ST_PreCharge_SW_HVS_01 "预充继电器驱动状态  备注：应用层的驱动指令信号";
CM_ SG_ 2332229441 ST_Main_POS_SW_HVS_01 "主正继电器驱动状态 备注：应用层的驱动指令信号";
CM_ SG_ 2332229441 ST_Main_NEG_SW_HVS_01 "主负继电器驱动状态 备注：应用层的驱动指令信号";
CM_ SG_ 2332229441 ST_System_01 "单柜是否允许上高压状态                                 未上高压前：0 为不允许上高压，1为允许上高压。上高压后：0为请求下高压，1为允许正常使用。";
CM_ SG_ 2332229441 ST_CALIBRATION_01 "单柜调试模式反馈                                   P2S调整报文发送（0x01 继电器指令，0x02 均衡指令，0x03 风机指令）信号的反馈状态，0是未接收相关的调试指令，1：接收到相关的调试指令";
CM_ SG_ 2332229441 ST_Insulation_01 "预留";
CM_ SG_ 2332229441 ST_PowerDown_01 "SBMU的供电输出低压电源状态                                                                           当前信号为低压相关的信号，发送的内部接口为：SeBMSM_LvPwrState 。含义为：SBMU低压电源运行状态反馈标志 ";
CM_ SG_ 2332229441 ST_pwr12V_01 "MCU反馈的12V电源pin应答状态";
CM_ SG_ 2332229441 ST_pwr5V_01 "预留";
CM_ SG_ 2332229441 ST_pwr24V_01 "通过MCU反馈的24V电源pin应答状态";
CM_ SG_ 2332229441 ST_pwrStatus_01 "单柜高压状态                                        当前为上高压完成信号：SbPRCC_HvPwrOnFinishFlg
 1,主正继电器的驱动指令为驱动闭合状态，且真实状态为闭合状态                                    2,主负继电器的驱动指令为驱动闭合状态，且真实状态为闭合状态                                     3, 预充继电器驱动指令为断开状态；                      同时满足条件1,2,3后保持1s 后该信号置为高压已上电
";
CM_ SG_ 2332229441 S2A_S2_FullChgFlgFromSBMU_01 "满充标志位";
CM_ SG_ 2332229441 ST_cscStandby_01 "CSC工作状态";
CM_ SG_ 2332229441 ST_OffReasonMsg_01 "主回路断开原因—每个bit代表一个原因，当前仅发送了前16个bit
 具体含义如下：
 Bit0: 高压无效Bit1:驱动短地Bit2:故障禁止上高压 forbid closeBit3:CSC编码中Bit4:概要数据中电压无效Bit5:概要数据温度无Bit6:预留调试模式（未使用）Bit7-Bit9: （未使用）Bit10: 未收到上高压指令Bit11: 故障强制断开继电器（force open）Bit12: 故障延迟断开继电器（normal Open）Bit13-Bit15: （未使用）";
CM_ SG_ 2332229442 CRC_S2A_S2_02 "S2A概要数据2 的CRC";
CM_ SG_ 2332229442 ALIV_ST_SW_HVS_02 "生命信号，0~15循环";
CM_ SG_ 2332229442 ST_PreCharge_SW_HVS_02 "预充继电器驱动状态  备注：应用层的驱动指令信号";
CM_ SG_ 2332229442 ST_Main_POS_SW_HVS_02 "主正继电器驱动状态 备注：应用层的驱动指令信号";
CM_ SG_ 2332229442 ST_Main_NEG_SW_HVS_02 "主负继电器驱动状态 备注：应用层的驱动指令信号";
CM_ SG_ 2332229442 ST_System_02 "单柜是否允许上高压状态                                 未上高压前：0 为不允许上高压，1为允许上高压。上高压后：0为请求下高压，1为允许正常使用。";
CM_ SG_ 2332229442 ST_CALIBRATION_02 "单柜调试模式反馈                                   P2S调整报文发送（0x01 继电器指令，0x02 均衡指令，0x03 风机指令）信号的反馈状态，0是未接收相关的调试指令，1：接收到相关的调试指令";
CM_ SG_ 2332229442 ST_Insulation_02 "预留";
CM_ SG_ 2332229442 ST_PowerDown_02 "SBMU的供电输出低压电源状态                                                                           当前信号为低压相关的信号，发送的内部接口为：SeBMSM_LvPwrState 。含义为：SBMU低压电源运行状态反馈标志 ";
CM_ SG_ 2332229442 ST_pwr12V_02 "MCU反馈的12V电源pin应答状态";
CM_ SG_ 2332229442 ST_pwr5V_02 "预留";
CM_ SG_ 2332229442 ST_pwr24V_02 "通过MCU反馈的24V电源pin应答状态";
CM_ SG_ 2332229442 ST_pwrStatus_02 "单柜高压状态                                        当前为上高压完成信号：SbPRCC_HvPwrOnFinishFlg
 1,主正继电器的驱动指令为驱动闭合状态，且真实状态为闭合状态                                    2,主负继电器的驱动指令为驱动闭合状态，且真实状态为闭合状态                                     3, 预充继电器驱动指令为断开状态；                      同时满足条件1,2,3后保持1s 后该信号置为高压已上电
";
CM_ SG_ 2332229442 S2A_S2_FullChgFlgFromSBMU_02 "满充标志位";
CM_ SG_ 2332229442 ST_cscStandby_02 "CSC工作状态";
CM_ SG_ 2332229442 ST_OffReasonMsg_02 "主回路断开原因—每个bit代表一个原因，当前仅发送了前16个bit
 具体含义如下：
 Bit0: 高压无效Bit1:驱动短地Bit2:故障禁止上高压 forbid closeBit3:CSC编码中Bit4:概要数据中电压无效Bit5:概要数据温度无Bit6:预留调试模式（未使用）Bit7-Bit9: （未使用）Bit10: 未收到上高压指令Bit11: 故障强制断开继电器（force open）Bit12: 故障延迟断开继电器（normal Open）Bit13-Bit15: （未使用）";
CM_ SG_ 2332229443 CRC_S2A_S2_03 "S2A概要数据2 的CRC";
CM_ SG_ 2332229443 ALIV_ST_SW_HVS_03 "生命信号，0~15循环";
CM_ SG_ 2332229443 ST_PreCharge_SW_HVS_03 "预充继电器驱动状态  备注：应用层的驱动指令信号";
CM_ SG_ 2332229443 ST_Main_POS_SW_HVS_03 "主正继电器驱动状态 备注：应用层的驱动指令信号";
CM_ SG_ 2332229443 ST_Main_NEG_SW_HVS_03 "主负继电器驱动状态 备注：应用层的驱动指令信号";
CM_ SG_ 2332229443 ST_System_03 "单柜是否允许上高压状态                                 未上高压前：0 为不允许上高压，1为允许上高压。上高压后：0为请求下高压，1为允许正常使用。";
CM_ SG_ 2332229443 ST_CALIBRATION_03 "单柜调试模式反馈                                   P2S调整报文发送（0x01 继电器指令，0x02 均衡指令，0x03 风机指令）信号的反馈状态，0是未接收相关的调试指令，1：接收到相关的调试指令";
CM_ SG_ 2332229443 ST_Insulation_03 "预留";
CM_ SG_ 2332229443 ST_PowerDown_03 "SBMU的供电输出低压电源状态                                                                           当前信号为低压相关的信号，发送的内部接口为：SeBMSM_LvPwrState 。含义为：SBMU低压电源运行状态反馈标志 ";
CM_ SG_ 2332229443 ST_pwr12V_03 "MCU反馈的12V电源pin应答状态";
CM_ SG_ 2332229443 ST_pwr5V_03 "预留";
CM_ SG_ 2332229443 ST_pwr24V_03 "通过MCU反馈的24V电源pin应答状态";
CM_ SG_ 2332229443 ST_pwrStatus_03 "单柜高压状态                                        当前为上高压完成信号：SbPRCC_HvPwrOnFinishFlg
 1,主正继电器的驱动指令为驱动闭合状态，且真实状态为闭合状态                                    2,主负继电器的驱动指令为驱动闭合状态，且真实状态为闭合状态                                     3, 预充继电器驱动指令为断开状态；                      同时满足条件1,2,3后保持1s 后该信号置为高压已上电
";
CM_ SG_ 2332229443 S2A_S2_FullChgFlgFromSBMU_03 "满充标志位";
CM_ SG_ 2332229443 ST_cscStandby_03 "CSC工作状态";
CM_ SG_ 2332229443 ST_OffReasonMsg_03 "主回路断开原因—每个bit代表一个原因，当前仅发送了前16个bit
 具体含义如下：
 Bit0: 高压无效Bit1:驱动短地Bit2:故障禁止上高压 forbid closeBit3:CSC编码中Bit4:概要数据中电压无效Bit5:概要数据温度无Bit6:预留调试模式（未使用）Bit7-Bit9: （未使用）Bit10: 未收到上高压指令Bit11: 故障强制断开继电器（force open）Bit12: 故障延迟断开继电器（normal Open）Bit13-Bit15: （未使用）";
CM_ SG_ 2332229444 CRC_S2A_S2_04 "S2A概要数据2 的CRC";
CM_ SG_ 2332229444 ALIV_ST_SW_HVS_04 "生命信号，0~15循环";
CM_ SG_ 2332229444 ST_PreCharge_SW_HVS_04 "预充继电器驱动状态  备注：应用层的驱动指令信号";
CM_ SG_ 2332229444 ST_Main_POS_SW_HVS_04 "主正继电器驱动状态 备注：应用层的驱动指令信号";
CM_ SG_ 2332229444 ST_Main_NEG_SW_HVS_04 "主负继电器驱动状态 备注：应用层的驱动指令信号";
CM_ SG_ 2332229444 ST_System_04 "单柜是否允许上高压状态                                 未上高压前：0 为不允许上高压，1为允许上高压。上高压后：0为请求下高压，1为允许正常使用。";
CM_ SG_ 2332229444 ST_CALIBRATION_04 "单柜调试模式反馈                                   P2S调整报文发送（0x01 继电器指令，0x02 均衡指令，0x03 风机指令）信号的反馈状态，0是未接收相关的调试指令，1：接收到相关的调试指令";
CM_ SG_ 2332229444 ST_Insulation_04 "预留";
CM_ SG_ 2332229444 ST_PowerDown_04 "SBMU的供电输出低压电源状态                                                                           当前信号为低压相关的信号，发送的内部接口为：SeBMSM_LvPwrState 。含义为：SBMU低压电源运行状态反馈标志 ";
CM_ SG_ 2332229444 ST_pwr12V_04 "MCU反馈的12V电源pin应答状态";
CM_ SG_ 2332229444 ST_pwr5V_04 "预留";
CM_ SG_ 2332229444 ST_pwr24V_04 "通过MCU反馈的24V电源pin应答状态";
CM_ SG_ 2332229444 ST_pwrStatus_04 "单柜高压状态                                        当前为上高压完成信号：SbPRCC_HvPwrOnFinishFlg
 1,主正继电器的驱动指令为驱动闭合状态，且真实状态为闭合状态                                    2,主负继电器的驱动指令为驱动闭合状态，且真实状态为闭合状态                                     3, 预充继电器驱动指令为断开状态；                      同时满足条件1,2,3后保持1s 后该信号置为高压已上电
";
CM_ SG_ 2332229444 S2A_S2_FullChgFlgFromSBMU_04 "满充标志位";
CM_ SG_ 2332229444 ST_cscStandby_04 "CSC工作状态";
CM_ SG_ 2332229444 ST_OffReasonMsg_04 "主回路断开原因—每个bit代表一个原因，当前仅发送了前16个bit
 具体含义如下：
 Bit0: 高压无效Bit1:驱动短地Bit2:故障禁止上高压 forbid closeBit3:CSC编码中Bit4:概要数据中电压无效Bit5:概要数据温度无Bit6:预留调试模式（未使用）Bit7-Bit9: （未使用）Bit10: 未收到上高压指令Bit11: 故障强制断开继电器（force open）Bit12: 故障延迟断开继电器（normal Open）Bit13-Bit15: （未使用）";
CM_ SG_ 2332229445 CRC_S2A_S2_05 "S2A概要数据2 的CRC";
CM_ SG_ 2332229445 ALIV_ST_SW_HVS_05 "生命信号，0~15循环";
CM_ SG_ 2332229445 ST_PreCharge_SW_HVS_05 "预充继电器驱动状态  备注：应用层的驱动指令信号";
CM_ SG_ 2332229445 ST_Main_POS_SW_HVS_05 "主正继电器驱动状态 备注：应用层的驱动指令信号";
CM_ SG_ 2332229445 ST_Main_NEG_SW_HVS_05 "主负继电器驱动状态 备注：应用层的驱动指令信号";
CM_ SG_ 2332229445 ST_System_05 "单柜是否允许上高压状态                                 未上高压前：0 为不允许上高压，1为允许上高压。上高压后：0为请求下高压，1为允许正常使用。";
CM_ SG_ 2332229445 ST_CALIBRATION_05 "单柜调试模式反馈                                   P2S调整报文发送（0x01 继电器指令，0x02 均衡指令，0x03 风机指令）信号的反馈状态，0是未接收相关的调试指令，1：接收到相关的调试指令";
CM_ SG_ 2332229445 ST_Insulation_05 "预留";
CM_ SG_ 2332229445 ST_PowerDown_05 "SBMU的供电输出低压电源状态                                                                           当前信号为低压相关的信号，发送的内部接口为：SeBMSM_LvPwrState 。含义为：SBMU低压电源运行状态反馈标志 ";
CM_ SG_ 2332229445 ST_pwr12V_05 "MCU反馈的12V电源pin应答状态";
CM_ SG_ 2332229445 ST_pwr5V_05 "预留";
CM_ SG_ 2332229445 ST_pwr24V_05 "通过MCU反馈的24V电源pin应答状态";
CM_ SG_ 2332229445 ST_pwrStatus_05 "单柜高压状态                                        当前为上高压完成信号：SbPRCC_HvPwrOnFinishFlg
 1,主正继电器的驱动指令为驱动闭合状态，且真实状态为闭合状态                                    2,主负继电器的驱动指令为驱动闭合状态，且真实状态为闭合状态                                     3, 预充继电器驱动指令为断开状态；                      同时满足条件1,2,3后保持1s 后该信号置为高压已上电
";
CM_ SG_ 2332229445 S2A_S2_FullChgFlgFromSBMU_05 "满充标志位";
CM_ SG_ 2332229445 ST_cscStandby_05 "CSC工作状态";
CM_ SG_ 2332229445 ST_OffReasonMsg_05 "主回路断开原因—每个bit代表一个原因，当前仅发送了前16个bit
 具体含义如下：
 Bit0: 高压无效Bit1:驱动短地Bit2:故障禁止上高压 forbid closeBit3:CSC编码中Bit4:概要数据中电压无效Bit5:概要数据温度无Bit6:预留调试模式（未使用）Bit7-Bit9: （未使用）Bit10: 未收到上高压指令Bit11: 故障强制断开继电器（force open）Bit12: 故障延迟断开继电器（normal Open）Bit13-Bit15: （未使用）";
CM_ SG_ 2332229446 CRC_S2A_S2_06 "S2A概要数据2 的CRC";
CM_ SG_ 2332229446 ALIV_ST_SW_HVS_06 "生命信号，0~15循环";
CM_ SG_ 2332229446 ST_PreCharge_SW_HVS_06 "预充继电器驱动状态  备注：应用层的驱动指令信号";
CM_ SG_ 2332229446 ST_Main_POS_SW_HVS_06 "主正继电器驱动状态 备注：应用层的驱动指令信号";
CM_ SG_ 2332229446 ST_Main_NEG_SW_HVS_06 "主负继电器驱动状态 备注：应用层的驱动指令信号";
CM_ SG_ 2332229446 ST_System_06 "单柜是否允许上高压状态                                 未上高压前：0 为不允许上高压，1为允许上高压。上高压后：0为请求下高压，1为允许正常使用。";
CM_ SG_ 2332229446 ST_CALIBRATION_06 "单柜调试模式反馈                                   P2S调整报文发送（0x01 继电器指令，0x02 均衡指令，0x03 风机指令）信号的反馈状态，0是未接收相关的调试指令，1：接收到相关的调试指令";
CM_ SG_ 2332229446 ST_Insulation_06 "预留";
CM_ SG_ 2332229446 ST_PowerDown_06 "SBMU的供电输出低压电源状态                                                                           当前信号为低压相关的信号，发送的内部接口为：SeBMSM_LvPwrState 。含义为：SBMU低压电源运行状态反馈标志 ";
CM_ SG_ 2332229446 ST_pwr12V_06 "MCU反馈的12V电源pin应答状态";
CM_ SG_ 2332229446 ST_pwr5V_06 "预留";
CM_ SG_ 2332229446 ST_pwr24V_06 "通过MCU反馈的24V电源pin应答状态";
CM_ SG_ 2332229446 ST_pwrStatus_06 "单柜高压状态                                        当前为上高压完成信号：SbPRCC_HvPwrOnFinishFlg
 1,主正继电器的驱动指令为驱动闭合状态，且真实状态为闭合状态                                    2,主负继电器的驱动指令为驱动闭合状态，且真实状态为闭合状态                                     3, 预充继电器驱动指令为断开状态；                      同时满足条件1,2,3后保持1s 后该信号置为高压已上电
";
CM_ SG_ 2332229446 S2A_S2_FullChgFlgFromSBMU_06 "满充标志位";
CM_ SG_ 2332229446 ST_cscStandby_06 "CSC工作状态";
CM_ SG_ 2332229446 ST_OffReasonMsg_06 "主回路断开原因—每个bit代表一个原因，当前仅发送了前16个bit
 具体含义如下：
 Bit0: 高压无效Bit1:驱动短地Bit2:故障禁止上高压 forbid closeBit3:CSC编码中Bit4:概要数据中电压无效Bit5:概要数据温度无Bit6:预留调试模式（未使用）Bit7-Bit9: （未使用）Bit10: 未收到上高压指令Bit11: 故障强制断开继电器（force open）Bit12: 故障延迟断开继电器（normal Open）Bit13-Bit15: （未使用）";
CM_ SG_ 2332229447 CRC_S2A_S2_07 "S2A概要数据2 的CRC";
CM_ SG_ 2332229447 ALIV_ST_SW_HVS_07 "生命信号，0~15循环";
CM_ SG_ 2332229447 ST_PreCharge_SW_HVS_07 "预充继电器驱动状态  备注：应用层的驱动指令信号";
CM_ SG_ 2332229447 ST_Main_POS_SW_HVS_07 "主正继电器驱动状态 备注：应用层的驱动指令信号";
CM_ SG_ 2332229447 ST_Main_NEG_SW_HVS_07 "主负继电器驱动状态 备注：应用层的驱动指令信号";
CM_ SG_ 2332229447 ST_System_07 "单柜是否允许上高压状态                                 未上高压前：0 为不允许上高压，1为允许上高压。上高压后：0为请求下高压，1为允许正常使用。";
CM_ SG_ 2332229447 ST_CALIBRATION_07 "单柜调试模式反馈                                   P2S调整报文发送（0x01 继电器指令，0x02 均衡指令，0x03 风机指令）信号的反馈状态，0是未接收相关的调试指令，1：接收到相关的调试指令";
CM_ SG_ 2332229447 ST_Insulation_07 "预留";
CM_ SG_ 2332229447 ST_PowerDown_07 "SBMU的供电输出低压电源状态                                                                           当前信号为低压相关的信号，发送的内部接口为：SeBMSM_LvPwrState 。含义为：SBMU低压电源运行状态反馈标志 ";
CM_ SG_ 2332229447 ST_pwr12V_07 "MCU反馈的12V电源pin应答状态";
CM_ SG_ 2332229447 ST_pwr5V_07 "预留";
CM_ SG_ 2332229447 ST_pwr24V_07 "通过MCU反馈的24V电源pin应答状态";
CM_ SG_ 2332229447 ST_pwrStatus_07 "单柜高压状态                                        当前为上高压完成信号：SbPRCC_HvPwrOnFinishFlg
 1,主正继电器的驱动指令为驱动闭合状态，且真实状态为闭合状态                                    2,主负继电器的驱动指令为驱动闭合状态，且真实状态为闭合状态                                     3, 预充继电器驱动指令为断开状态；                      同时满足条件1,2,3后保持1s 后该信号置为高压已上电
";
CM_ SG_ 2332229447 S2A_S2_FullChgFlgFromSBMU_07 "满充标志位";
CM_ SG_ 2332229447 ST_cscStandby_07 "CSC工作状态";
CM_ SG_ 2332229447 ST_OffReasonMsg_07 "主回路断开原因—每个bit代表一个原因，当前仅发送了前16个bit
 具体含义如下：
 Bit0: 高压无效Bit1:驱动短地Bit2:故障禁止上高压 forbid closeBit3:CSC编码中Bit4:概要数据中电压无效Bit5:概要数据温度无Bit6:预留调试模式（未使用）Bit7-Bit9: （未使用）Bit10: 未收到上高压指令Bit11: 故障强制断开继电器（force open）Bit12: 故障延迟断开继电器（normal Open）Bit13-Bit15: （未使用）";
CM_ SG_ 2332229448 CRC_S2A_S2_08 "S2A概要数据2 的CRC";
CM_ SG_ 2332229448 ALIV_ST_SW_HVS_08 "生命信号，0~15循环";
CM_ SG_ 2332229448 ST_PreCharge_SW_HVS_08 "预充继电器驱动状态  备注：应用层的驱动指令信号";
CM_ SG_ 2332229448 ST_Main_POS_SW_HVS_08 "主正继电器驱动状态 备注：应用层的驱动指令信号";
CM_ SG_ 2332229448 ST_Main_NEG_SW_HVS_08 "主负继电器驱动状态 备注：应用层的驱动指令信号";
CM_ SG_ 2332229448 ST_System_08 "单柜是否允许上高压状态                                 未上高压前：0 为不允许上高压，1为允许上高压。上高压后：0为请求下高压，1为允许正常使用。";
CM_ SG_ 2332229448 ST_CALIBRATION_08 "单柜调试模式反馈                                   P2S调整报文发送（0x01 继电器指令，0x02 均衡指令，0x03 风机指令）信号的反馈状态，0是未接收相关的调试指令，1：接收到相关的调试指令";
CM_ SG_ 2332229448 ST_Insulation_08 "预留";
CM_ SG_ 2332229448 ST_PowerDown_08 "SBMU的供电输出低压电源状态                                                                           当前信号为低压相关的信号，发送的内部接口为：SeBMSM_LvPwrState 。含义为：SBMU低压电源运行状态反馈标志 ";
CM_ SG_ 2332229448 ST_pwr12V_08 "MCU反馈的12V电源pin应答状态";
CM_ SG_ 2332229448 ST_pwr5V_08 "预留";
CM_ SG_ 2332229448 ST_pwr24V_08 "通过MCU反馈的24V电源pin应答状态";
CM_ SG_ 2332229448 ST_pwrStatus_08 "单柜高压状态                                        当前为上高压完成信号：SbPRCC_HvPwrOnFinishFlg
 1,主正继电器的驱动指令为驱动闭合状态，且真实状态为闭合状态                                    2,主负继电器的驱动指令为驱动闭合状态，且真实状态为闭合状态                                     3, 预充继电器驱动指令为断开状态；                      同时满足条件1,2,3后保持1s 后该信号置为高压已上电
";
CM_ SG_ 2332229448 S2A_S2_FullChgFlgFromSBMU_08 "满充标志位";
CM_ SG_ 2332229448 ST_cscStandby_08 "CSC工作状态";
CM_ SG_ 2332229448 ST_OffReasonMsg_08 "主回路断开原因—每个bit代表一个原因，当前仅发送了前16个bit
 具体含义如下：
 Bit0: 高压无效Bit1:驱动短地Bit2:故障禁止上高压 forbid closeBit3:CSC编码中Bit4:概要数据中电压无效Bit5:概要数据温度无Bit6:预留调试模式（未使用）Bit7-Bit9: （未使用）Bit10: 未收到上高压指令Bit11: 故障强制断开继电器（force open）Bit12: 故障延迟断开继电器（normal Open）Bit13-Bit15: （未使用）";
CM_ SG_ 2332229449 CRC_S2A_S2_09 "S2A概要数据2 的CRC";
CM_ SG_ 2332229449 ALIV_ST_SW_HVS_09 "生命信号，0~15循环";
CM_ SG_ 2332229449 ST_PreCharge_SW_HVS_09 "预充继电器驱动状态  备注：应用层的驱动指令信号";
CM_ SG_ 2332229449 ST_Main_POS_SW_HVS_09 "主正继电器驱动状态 备注：应用层的驱动指令信号";
CM_ SG_ 2332229449 ST_Main_NEG_SW_HVS_09 "主负继电器驱动状态 备注：应用层的驱动指令信号";
CM_ SG_ 2332229449 ST_System_09 "单柜是否允许上高压状态                                 未上高压前：0 为不允许上高压，1为允许上高压。上高压后：0为请求下高压，1为允许正常使用。";
CM_ SG_ 2332229449 ST_CALIBRATION_09 "单柜调试模式反馈                                   P2S调整报文发送（0x01 继电器指令，0x02 均衡指令，0x03 风机指令）信号的反馈状态，0是未接收相关的调试指令，1：接收到相关的调试指令";
CM_ SG_ 2332229449 ST_Insulation_09 "预留";
CM_ SG_ 2332229449 ST_PowerDown_09 "SBMU的供电输出低压电源状态                                                                           当前信号为低压相关的信号，发送的内部接口为：SeBMSM_LvPwrState 。含义为：SBMU低压电源运行状态反馈标志 ";
CM_ SG_ 2332229449 ST_pwr12V_09 "MCU反馈的12V电源pin应答状态";
CM_ SG_ 2332229449 ST_pwr5V_09 "预留";
CM_ SG_ 2332229449 ST_pwr24V_09 "通过MCU反馈的24V电源pin应答状态";
CM_ SG_ 2332229449 ST_pwrStatus_09 "单柜高压状态                                        当前为上高压完成信号：SbPRCC_HvPwrOnFinishFlg
 1,主正继电器的驱动指令为驱动闭合状态，且真实状态为闭合状态                                    2,主负继电器的驱动指令为驱动闭合状态，且真实状态为闭合状态                                     3, 预充继电器驱动指令为断开状态；                      同时满足条件1,2,3后保持1s 后该信号置为高压已上电
";
CM_ SG_ 2332229449 S2A_S2_FullChgFlgFromSBMU_09 "满充标志位";
CM_ SG_ 2332229449 ST_cscStandby_09 "CSC工作状态";
CM_ SG_ 2332229449 ST_OffReasonMsg_09 "主回路断开原因—每个bit代表一个原因，当前仅发送了前16个bit
 具体含义如下：
 Bit0: 高压无效Bit1:驱动短地Bit2:故障禁止上高压 forbid closeBit3:CSC编码中Bit4:概要数据中电压无效Bit5:概要数据温度无Bit6:预留调试模式（未使用）Bit7-Bit9: （未使用）Bit10: 未收到上高压指令Bit11: 故障强制断开继电器（force open）Bit12: 故障延迟断开继电器（normal Open）Bit13-Bit15: （未使用）";
CM_ SG_ 2332229450 CRC_S2A_S2_10 "S2A概要数据2 的CRC";
CM_ SG_ 2332229450 ALIV_ST_SW_HVS_10 "生命信号，0~15循环";
CM_ SG_ 2332229450 ST_PreCharge_SW_HVS_10 "预充继电器驱动状态  备注：应用层的驱动指令信号";
CM_ SG_ 2332229450 ST_Main_POS_SW_HVS_10 "主正继电器驱动状态 备注：应用层的驱动指令信号";
CM_ SG_ 2332229450 ST_Main_NEG_SW_HVS_10 "主负继电器驱动状态 备注：应用层的驱动指令信号";
CM_ SG_ 2332229450 ST_System_10 "单柜是否允许上高压状态                                 未上高压前：0 为不允许上高压，1为允许上高压。上高压后：0为请求下高压，1为允许正常使用。";
CM_ SG_ 2332229450 ST_CALIBRATION_10 "单柜调试模式反馈                                   P2S调整报文发送（0x01 继电器指令，0x02 均衡指令，0x03 风机指令）信号的反馈状态，0是未接收相关的调试指令，1：接收到相关的调试指令";
CM_ SG_ 2332229450 ST_Insulation_10 "预留";
CM_ SG_ 2332229450 ST_PowerDown_10 "SBMU的供电输出低压电源状态                                                                           当前信号为低压相关的信号，发送的内部接口为：SeBMSM_LvPwrState 。含义为：SBMU低压电源运行状态反馈标志 ";
CM_ SG_ 2332229450 ST_pwr12V_10 "MCU反馈的12V电源pin应答状态";
CM_ SG_ 2332229450 ST_pwr5V_10 "预留";
CM_ SG_ 2332229450 ST_pwr24V_10 "通过MCU反馈的24V电源pin应答状态";
CM_ SG_ 2332229450 ST_pwrStatus_10 "单柜高压状态                                        当前为上高压完成信号：SbPRCC_HvPwrOnFinishFlg
 1,主正继电器的驱动指令为驱动闭合状态，且真实状态为闭合状态                                    2,主负继电器的驱动指令为驱动闭合状态，且真实状态为闭合状态                                     3, 预充继电器驱动指令为断开状态；                      同时满足条件1,2,3后保持1s 后该信号置为高压已上电
";
CM_ SG_ 2332229450 S2A_S2_FullChgFlgFromSBMU_10 "满充标志位";
CM_ SG_ 2332229450 ST_cscStandby_10 "CSC工作状态";
CM_ SG_ 2332229450 ST_OffReasonMsg_10 "主回路断开原因—每个bit代表一个原因，当前仅发送了前16个bit
 具体含义如下：
 Bit0: 高压无效Bit1:驱动短地Bit2:故障禁止上高压 forbid closeBit3:CSC编码中Bit4:概要数据中电压无效Bit5:概要数据温度无Bit6:预留调试模式（未使用）Bit7-Bit9: （未使用）Bit10: 未收到上高压指令Bit11: 故障强制断开继电器（force open）Bit12: 故障延迟断开继电器（normal Open）Bit13-Bit15: （未使用）";
CM_ SG_ 2332229451 CRC_S2A_S2_11 "S2A概要数据2 的CRC";
CM_ SG_ 2332229451 ALIV_ST_SW_HVS_11 "生命信号，0~15循环";
CM_ SG_ 2332229451 ST_PreCharge_SW_HVS_11 "预充继电器驱动状态  备注：应用层的驱动指令信号";
CM_ SG_ 2332229451 ST_Main_POS_SW_HVS_11 "主正继电器驱动状态 备注：应用层的驱动指令信号";
CM_ SG_ 2332229451 ST_Main_NEG_SW_HVS_11 "主负继电器驱动状态 备注：应用层的驱动指令信号";
CM_ SG_ 2332229451 ST_System_11 "单柜是否允许上高压状态                                 未上高压前：0 为不允许上高压，1为允许上高压。上高压后：0为请求下高压，1为允许正常使用。";
CM_ SG_ 2332229451 ST_CALIBRATION_11 "单柜调试模式反馈                                   P2S调整报文发送（0x01 继电器指令，0x02 均衡指令，0x03 风机指令）信号的反馈状态，0是未接收相关的调试指令，1：接收到相关的调试指令";
CM_ SG_ 2332229451 ST_Insulation_11 "预留";
CM_ SG_ 2332229451 ST_PowerDown_11 "SBMU的供电输出低压电源状态                                                                           当前信号为低压相关的信号，发送的内部接口为：SeBMSM_LvPwrState 。含义为：SBMU低压电源运行状态反馈标志 ";
CM_ SG_ 2332229451 ST_pwr12V_11 "MCU反馈的12V电源pin应答状态";
CM_ SG_ 2332229451 ST_pwr5V_11 "预留";
CM_ SG_ 2332229451 ST_pwr24V_11 "通过MCU反馈的24V电源pin应答状态";
CM_ SG_ 2332229451 ST_pwrStatus_11 "单柜高压状态                                        当前为上高压完成信号：SbPRCC_HvPwrOnFinishFlg
 1,主正继电器的驱动指令为驱动闭合状态，且真实状态为闭合状态                                    2,主负继电器的驱动指令为驱动闭合状态，且真实状态为闭合状态                                     3, 预充继电器驱动指令为断开状态；                      同时满足条件1,2,3后保持1s 后该信号置为高压已上电
";
CM_ SG_ 2332229451 S2A_S2_FullChgFlgFromSBMU_11 "满充标志位";
CM_ SG_ 2332229451 ST_cscStandby_11 "CSC工作状态";
CM_ SG_ 2332229451 ST_OffReasonMsg_11 "主回路断开原因—每个bit代表一个原因，当前仅发送了前16个bit
 具体含义如下：
 Bit0: 高压无效Bit1:驱动短地Bit2:故障禁止上高压 forbid closeBit3:CSC编码中Bit4:概要数据中电压无效Bit5:概要数据温度无Bit6:预留调试模式（未使用）Bit7-Bit9: （未使用）Bit10: 未收到上高压指令Bit11: 故障强制断开继电器（force open）Bit12: 故障延迟断开继电器（normal Open）Bit13-Bit15: （未使用）";
CM_ SG_ 2332229452 CRC_S2A_S2_12 "S2A概要数据2 的CRC";
CM_ SG_ 2332229452 ALIV_ST_SW_HVS_12 "生命信号，0~15循环";
CM_ SG_ 2332229452 ST_PreCharge_SW_HVS_12 "预充继电器驱动状态  备注：应用层的驱动指令信号";
CM_ SG_ 2332229452 ST_Main_POS_SW_HVS_12 "主正继电器驱动状态 备注：应用层的驱动指令信号";
CM_ SG_ 2332229452 ST_Main_NEG_SW_HVS_12 "主负继电器驱动状态 备注：应用层的驱动指令信号";
CM_ SG_ 2332229452 ST_System_12 "单柜是否允许上高压状态                                 未上高压前：0 为不允许上高压，1为允许上高压。上高压后：0为请求下高压，1为允许正常使用。";
CM_ SG_ 2332229452 ST_CALIBRATION_12 "单柜调试模式反馈                                   P2S调整报文发送（0x01 继电器指令，0x02 均衡指令，0x03 风机指令）信号的反馈状态，0是未接收相关的调试指令，1：接收到相关的调试指令";
CM_ SG_ 2332229452 ST_Insulation_12 "预留";
CM_ SG_ 2332229452 ST_PowerDown_12 "SBMU的供电输出低压电源状态                                                                           当前信号为低压相关的信号，发送的内部接口为：SeBMSM_LvPwrState 。含义为：SBMU低压电源运行状态反馈标志 ";
CM_ SG_ 2332229452 ST_pwr12V_12 "MCU反馈的12V电源pin应答状态";
CM_ SG_ 2332229452 ST_pwr5V_12 "预留";
CM_ SG_ 2332229452 ST_pwr24V_12 "通过MCU反馈的24V电源pin应答状态";
CM_ SG_ 2332229452 ST_pwrStatus_12 "单柜高压状态                                        当前为上高压完成信号：SbPRCC_HvPwrOnFinishFlg
 1,主正继电器的驱动指令为驱动闭合状态，且真实状态为闭合状态                                    2,主负继电器的驱动指令为驱动闭合状态，且真实状态为闭合状态                                     3, 预充继电器驱动指令为断开状态；                      同时满足条件1,2,3后保持1s 后该信号置为高压已上电
";
CM_ SG_ 2332229452 S2A_S2_FullChgFlgFromSBMU_12 "满充标志位";
CM_ SG_ 2332229452 ST_cscStandby_12 "CSC工作状态";
CM_ SG_ 2332229452 ST_OffReasonMsg_12 "主回路断开原因—每个bit代表一个原因，当前仅发送了前16个bit
 具体含义如下：
 Bit0: 高压无效Bit1:驱动短地Bit2:故障禁止上高压 forbid closeBit3:CSC编码中Bit4:概要数据中电压无效Bit5:概要数据温度无Bit6:预留调试模式（未使用）Bit7-Bit9: （未使用）Bit10: 未收到上高压指令Bit11: 故障强制断开继电器（force open）Bit12: 故障延迟断开继电器（normal Open）Bit13-Bit15: （未使用）";
CM_ SG_ 2332229453 CRC_S2A_S2_13 "S2A概要数据2 的CRC";
CM_ SG_ 2332229453 ALIV_ST_SW_HVS_13 "生命信号，0~15循环";
CM_ SG_ 2332229453 ST_PreCharge_SW_HVS_13 "预充继电器驱动状态  备注：应用层的驱动指令信号";
CM_ SG_ 2332229453 ST_Main_POS_SW_HVS_13 "主正继电器驱动状态 备注：应用层的驱动指令信号";
CM_ SG_ 2332229453 ST_Main_NEG_SW_HVS_13 "主负继电器驱动状态 备注：应用层的驱动指令信号";
CM_ SG_ 2332229453 ST_System_13 "单柜是否允许上高压状态                                 未上高压前：0 为不允许上高压，1为允许上高压。上高压后：0为请求下高压，1为允许正常使用。";
CM_ SG_ 2332229453 ST_CALIBRATION_13 "单柜调试模式反馈                                   P2S调整报文发送（0x01 继电器指令，0x02 均衡指令，0x03 风机指令）信号的反馈状态，0是未接收相关的调试指令，1：接收到相关的调试指令";
CM_ SG_ 2332229453 ST_Insulation_13 "预留";
CM_ SG_ 2332229453 ST_PowerDown_13 "SBMU的供电输出低压电源状态                                                                           当前信号为低压相关的信号，发送的内部接口为：SeBMSM_LvPwrState 。含义为：SBMU低压电源运行状态反馈标志 ";
CM_ SG_ 2332229453 ST_pwr12V_13 "MCU反馈的12V电源pin应答状态";
CM_ SG_ 2332229453 ST_pwr5V_13 "预留";
CM_ SG_ 2332229453 ST_pwr24V_13 "通过MCU反馈的24V电源pin应答状态";
CM_ SG_ 2332229453 ST_pwrStatus_13 "单柜高压状态                                        当前为上高压完成信号：SbPRCC_HvPwrOnFinishFlg
 1,主正继电器的驱动指令为驱动闭合状态，且真实状态为闭合状态                                    2,主负继电器的驱动指令为驱动闭合状态，且真实状态为闭合状态                                     3, 预充继电器驱动指令为断开状态；                      同时满足条件1,2,3后保持1s 后该信号置为高压已上电
";
CM_ SG_ 2332229453 S2A_S2_FullChgFlgFromSBMU_13 "满充标志位";
CM_ SG_ 2332229453 ST_cscStandby_13 "CSC工作状态";
CM_ SG_ 2332229453 ST_OffReasonMsg_13 "主回路断开原因—每个bit代表一个原因，当前仅发送了前16个bit
 具体含义如下：
 Bit0: 高压无效Bit1:驱动短地Bit2:故障禁止上高压 forbid closeBit3:CSC编码中Bit4:概要数据中电压无效Bit5:概要数据温度无Bit6:预留调试模式（未使用）Bit7-Bit9: （未使用）Bit10: 未收到上高压指令Bit11: 故障强制断开继电器（force open）Bit12: 故障延迟断开继电器（normal Open）Bit13-Bit15: （未使用）";
CM_ SG_ 2332229454 CRC_S2A_S2_14 "S2A概要数据2 的CRC";
CM_ SG_ 2332229454 ALIV_ST_SW_HVS_14 "生命信号，0~15循环";
CM_ SG_ 2332229454 ST_PreCharge_SW_HVS_14 "预充继电器驱动状态  备注：应用层的驱动指令信号";
CM_ SG_ 2332229454 ST_Main_POS_SW_HVS_14 "主正继电器驱动状态 备注：应用层的驱动指令信号";
CM_ SG_ 2332229454 ST_Main_NEG_SW_HVS_14 "主负继电器驱动状态 备注：应用层的驱动指令信号";
CM_ SG_ 2332229454 ST_System_14 "单柜是否允许上高压状态                                 未上高压前：0 为不允许上高压，1为允许上高压。上高压后：0为请求下高压，1为允许正常使用。";
CM_ SG_ 2332229454 ST_CALIBRATION_14 "单柜调试模式反馈                                   P2S调整报文发送（0x01 继电器指令，0x02 均衡指令，0x03 风机指令）信号的反馈状态，0是未接收相关的调试指令，1：接收到相关的调试指令";
CM_ SG_ 2332229454 ST_Insulation_14 "预留";
CM_ SG_ 2332229454 ST_PowerDown_14 "SBMU的供电输出低压电源状态                                                                           当前信号为低压相关的信号，发送的内部接口为：SeBMSM_LvPwrState 。含义为：SBMU低压电源运行状态反馈标志 ";
CM_ SG_ 2332229454 ST_pwr12V_14 "MCU反馈的12V电源pin应答状态";
CM_ SG_ 2332229454 ST_pwr5V_14 "预留";
CM_ SG_ 2332229454 ST_pwr24V_14 "通过MCU反馈的24V电源pin应答状态";
CM_ SG_ 2332229454 ST_pwrStatus_14 "单柜高压状态                                        当前为上高压完成信号：SbPRCC_HvPwrOnFinishFlg
 1,主正继电器的驱动指令为驱动闭合状态，且真实状态为闭合状态                                    2,主负继电器的驱动指令为驱动闭合状态，且真实状态为闭合状态                                     3, 预充继电器驱动指令为断开状态；                      同时满足条件1,2,3后保持1s 后该信号置为高压已上电
";
CM_ SG_ 2332229454 S2A_S2_FullChgFlgFromSBMU_14 "满充标志位";
CM_ SG_ 2332229454 ST_cscStandby_14 "CSC工作状态";
CM_ SG_ 2332229454 ST_OffReasonMsg_14 "主回路断开原因—每个bit代表一个原因，当前仅发送了前16个bit
 具体含义如下：
 Bit0: 高压无效Bit1:驱动短地Bit2:故障禁止上高压 forbid closeBit3:CSC编码中Bit4:概要数据中电压无效Bit5:概要数据温度无Bit6:预留调试模式（未使用）Bit7-Bit9: （未使用）Bit10: 未收到上高压指令Bit11: 故障强制断开继电器（force open）Bit12: 故障延迟断开继电器（normal Open）Bit13-Bit15: （未使用）";
CM_ SG_ 2332229455 CRC_S2A_S2_15 "S2A概要数据2 的CRC";
CM_ SG_ 2332229455 ALIV_ST_SW_HVS_15 "生命信号，0~15循环";
CM_ SG_ 2332229455 ST_PreCharge_SW_HVS_15 "预充继电器驱动状态  备注：应用层的驱动指令信号";
CM_ SG_ 2332229455 ST_Main_POS_SW_HVS_15 "主正继电器驱动状态 备注：应用层的驱动指令信号";
CM_ SG_ 2332229455 ST_Main_NEG_SW_HVS_15 "主负继电器驱动状态 备注：应用层的驱动指令信号";
CM_ SG_ 2332229455 ST_System_15 "单柜是否允许上高压状态                                 未上高压前：0 为不允许上高压，1为允许上高压。上高压后：0为请求下高压，1为允许正常使用。";
CM_ SG_ 2332229455 ST_CALIBRATION_15 "单柜调试模式反馈                                   P2S调整报文发送（0x01 继电器指令，0x02 均衡指令，0x03 风机指令）信号的反馈状态，0是未接收相关的调试指令，1：接收到相关的调试指令";
CM_ SG_ 2332229455 ST_Insulation_15 "预留";
CM_ SG_ 2332229455 ST_PowerDown_15 "SBMU的供电输出低压电源状态                                                                           当前信号为低压相关的信号，发送的内部接口为：SeBMSM_LvPwrState 。含义为：SBMU低压电源运行状态反馈标志 ";
CM_ SG_ 2332229455 ST_pwr12V_15 "MCU反馈的12V电源pin应答状态";
CM_ SG_ 2332229455 ST_pwr5V_15 "预留";
CM_ SG_ 2332229455 ST_pwr24V_15 "通过MCU反馈的24V电源pin应答状态";
CM_ SG_ 2332229455 ST_pwrStatus_15 "单柜高压状态                                        当前为上高压完成信号：SbPRCC_HvPwrOnFinishFlg
 1,主正继电器的驱动指令为驱动闭合状态，且真实状态为闭合状态                                    2,主负继电器的驱动指令为驱动闭合状态，且真实状态为闭合状态                                     3, 预充继电器驱动指令为断开状态；                      同时满足条件1,2,3后保持1s 后该信号置为高压已上电
";
CM_ SG_ 2332229455 S2A_S2_FullChgFlgFromSBMU_15 "满充标志位";
CM_ SG_ 2332229455 ST_cscStandby_15 "CSC工作状态";
CM_ SG_ 2332229455 ST_OffReasonMsg_15 "主回路断开原因—每个bit代表一个原因，当前仅发送了前16个bit
 具体含义如下：
 Bit0: 高压无效Bit1:驱动短地Bit2:故障禁止上高压 forbid closeBit3:CSC编码中Bit4:概要数据中电压无效Bit5:概要数据温度无Bit6:预留调试模式（未使用）Bit7-Bit9: （未使用）Bit10: 未收到上高压指令Bit11: 故障强制断开继电器（force open）Bit12: 故障延迟断开继电器（normal Open）Bit13-Bit15: （未使用）";
CM_ SG_ 2332229456 CRC_S2A_S2_16 "S2A概要数据2 的CRC";
CM_ SG_ 2332229456 ALIV_ST_SW_HVS_16 "生命信号，0~15循环";
CM_ SG_ 2332229456 ST_PreCharge_SW_HVS_16 "预充继电器驱动状态  备注：应用层的驱动指令信号";
CM_ SG_ 2332229456 ST_Main_POS_SW_HVS_16 "主正继电器驱动状态 备注：应用层的驱动指令信号";
CM_ SG_ 2332229456 ST_Main_NEG_SW_HVS_16 "主负继电器驱动状态 备注：应用层的驱动指令信号";
CM_ SG_ 2332229456 ST_System_16 "单柜是否允许上高压状态                                 未上高压前：0 为不允许上高压，1为允许上高压。上高压后：0为请求下高压，1为允许正常使用。";
CM_ SG_ 2332229456 ST_CALIBRATION_16 "单柜调试模式反馈                                   P2S调整报文发送（0x01 继电器指令，0x02 均衡指令，0x03 风机指令）信号的反馈状态，0是未接收相关的调试指令，1：接收到相关的调试指令";
CM_ SG_ 2332229456 ST_Insulation_16 "预留";
CM_ SG_ 2332229456 ST_PowerDown_16 "SBMU的供电输出低压电源状态                                                                           当前信号为低压相关的信号，发送的内部接口为：SeBMSM_LvPwrState 。含义为：SBMU低压电源运行状态反馈标志 ";
CM_ SG_ 2332229456 ST_pwr12V_16 "MCU反馈的12V电源pin应答状态";
CM_ SG_ 2332229456 ST_pwr5V_16 "预留";
CM_ SG_ 2332229456 ST_pwr24V_16 "通过MCU反馈的24V电源pin应答状态";
CM_ SG_ 2332229456 ST_pwrStatus_16 "单柜高压状态                                        当前为上高压完成信号：SbPRCC_HvPwrOnFinishFlg
 1,主正继电器的驱动指令为驱动闭合状态，且真实状态为闭合状态                                    2,主负继电器的驱动指令为驱动闭合状态，且真实状态为闭合状态                                     3, 预充继电器驱动指令为断开状态；                      同时满足条件1,2,3后保持1s 后该信号置为高压已上电
";
CM_ SG_ 2332229456 S2A_S2_FullChgFlgFromSBMU_16 "满充标志位";
CM_ SG_ 2332229456 ST_cscStandby_16 "CSC工作状态";
CM_ SG_ 2332229456 ST_OffReasonMsg_16 "主回路断开原因—每个bit代表一个原因，当前仅发送了前16个bit
 具体含义如下：
 Bit0: 高压无效Bit1:驱动短地Bit2:故障禁止上高压 forbid closeBit3:CSC编码中Bit4:概要数据中电压无效Bit5:概要数据温度无Bit6:预留调试模式（未使用）Bit7-Bit9: （未使用）Bit10: 未收到上高压指令Bit11: 故障强制断开继电器（force open）Bit12: 故障延迟断开继电器（normal Open）Bit13-Bit15: （未使用）";
CM_ SG_ 2332229457 CRC_S2A_S2_17 "S2A概要数据2 的CRC";
CM_ SG_ 2332229457 ALIV_ST_SW_HVS_17 "生命信号，0~15循环";
CM_ SG_ 2332229457 ST_PreCharge_SW_HVS_17 "预充继电器驱动状态  备注：应用层的驱动指令信号";
CM_ SG_ 2332229457 ST_Main_POS_SW_HVS_17 "主正继电器驱动状态 备注：应用层的驱动指令信号";
CM_ SG_ 2332229457 ST_Main_NEG_SW_HVS_17 "主负继电器驱动状态 备注：应用层的驱动指令信号";
CM_ SG_ 2332229457 ST_System_17 "单柜是否允许上高压状态                                 未上高压前：0 为不允许上高压，1为允许上高压。上高压后：0为请求下高压，1为允许正常使用。";
CM_ SG_ 2332229457 ST_CALIBRATION_17 "单柜调试模式反馈                                   P2S调整报文发送（0x01 继电器指令，0x02 均衡指令，0x03 风机指令）信号的反馈状态，0是未接收相关的调试指令，1：接收到相关的调试指令";
CM_ SG_ 2332229457 ST_Insulation_17 "预留";
CM_ SG_ 2332229457 ST_PowerDown_17 "SBMU的供电输出低压电源状态                                                                           当前信号为低压相关的信号，发送的内部接口为：SeBMSM_LvPwrState 。含义为：SBMU低压电源运行状态反馈标志 ";
CM_ SG_ 2332229457 ST_pwr12V_17 "MCU反馈的12V电源pin应答状态";
CM_ SG_ 2332229457 ST_pwr5V_17 "预留";
CM_ SG_ 2332229457 ST_pwr24V_17 "通过MCU反馈的24V电源pin应答状态";
CM_ SG_ 2332229457 ST_pwrStatus_17 "单柜高压状态                                        当前为上高压完成信号：SbPRCC_HvPwrOnFinishFlg
 1,主正继电器的驱动指令为驱动闭合状态，且真实状态为闭合状态                                    2,主负继电器的驱动指令为驱动闭合状态，且真实状态为闭合状态                                     3, 预充继电器驱动指令为断开状态；                      同时满足条件1,2,3后保持1s 后该信号置为高压已上电
";
CM_ SG_ 2332229457 S2A_S2_FullChgFlgFromSBMU_17 "满充标志位";
CM_ SG_ 2332229457 ST_cscStandby_17 "CSC工作状态";
CM_ SG_ 2332229457 ST_OffReasonMsg_17 "主回路断开原因—每个bit代表一个原因，当前仅发送了前16个bit
 具体含义如下：
 Bit0: 高压无效Bit1:驱动短地Bit2:故障禁止上高压 forbid closeBit3:CSC编码中Bit4:概要数据中电压无效Bit5:概要数据温度无Bit6:预留调试模式（未使用）Bit7-Bit9: （未使用）Bit10: 未收到上高压指令Bit11: 故障强制断开继电器（force open）Bit12: 故障延迟断开继电器（normal Open）Bit13-Bit15: （未使用）";
CM_ SG_ 2332229458 CRC_S2A_S2_18 "S2A概要数据2 的CRC";
CM_ SG_ 2332229458 ALIV_ST_SW_HVS_18 "生命信号，0~15循环";
CM_ SG_ 2332229458 ST_PreCharge_SW_HVS_18 "预充继电器驱动状态  备注：应用层的驱动指令信号";
CM_ SG_ 2332229458 ST_Main_POS_SW_HVS_18 "主正继电器驱动状态 备注：应用层的驱动指令信号";
CM_ SG_ 2332229458 ST_Main_NEG_SW_HVS_18 "主负继电器驱动状态 备注：应用层的驱动指令信号";
CM_ SG_ 2332229458 ST_System_18 "单柜是否允许上高压状态                                 未上高压前：0 为不允许上高压，1为允许上高压。上高压后：0为请求下高压，1为允许正常使用。";
CM_ SG_ 2332229458 ST_CALIBRATION_18 "单柜调试模式反馈                                   P2S调整报文发送（0x01 继电器指令，0x02 均衡指令，0x03 风机指令）信号的反馈状态，0是未接收相关的调试指令，1：接收到相关的调试指令";
CM_ SG_ 2332229458 ST_Insulation_18 "预留";
CM_ SG_ 2332229458 ST_PowerDown_18 "SBMU的供电输出低压电源状态                                                                           当前信号为低压相关的信号，发送的内部接口为：SeBMSM_LvPwrState 。含义为：SBMU低压电源运行状态反馈标志 ";
CM_ SG_ 2332229458 ST_pwr12V_18 "MCU反馈的12V电源pin应答状态";
CM_ SG_ 2332229458 ST_pwr5V_18 "预留";
CM_ SG_ 2332229458 ST_pwr24V_18 "通过MCU反馈的24V电源pin应答状态";
CM_ SG_ 2332229458 ST_pwrStatus_18 "单柜高压状态                                        当前为上高压完成信号：SbPRCC_HvPwrOnFinishFlg
 1,主正继电器的驱动指令为驱动闭合状态，且真实状态为闭合状态                                    2,主负继电器的驱动指令为驱动闭合状态，且真实状态为闭合状态                                     3, 预充继电器驱动指令为断开状态；                      同时满足条件1,2,3后保持1s 后该信号置为高压已上电
";
CM_ SG_ 2332229458 S2A_S2_FullChgFlgFromSBMU_18 "满充标志位";
CM_ SG_ 2332229458 ST_cscStandby_18 "CSC工作状态";
CM_ SG_ 2332229458 ST_OffReasonMsg_18 "主回路断开原因—每个bit代表一个原因，当前仅发送了前16个bit
 具体含义如下：
 Bit0: 高压无效Bit1:驱动短地Bit2:故障禁止上高压 forbid closeBit3:CSC编码中Bit4:概要数据中电压无效Bit5:概要数据温度无Bit6:预留调试模式（未使用）Bit7-Bit9: （未使用）Bit10: 未收到上高压指令Bit11: 故障强制断开继电器（force open）Bit12: 故障延迟断开继电器（normal Open）Bit13-Bit15: （未使用）";
CM_ SG_ 2332229459 CRC_S2A_S2_19 "S2A概要数据2 的CRC";
CM_ SG_ 2332229459 ALIV_ST_SW_HVS_19 "生命信号，0~15循环";
CM_ SG_ 2332229459 ST_PreCharge_SW_HVS_19 "预充继电器驱动状态  备注：应用层的驱动指令信号";
CM_ SG_ 2332229459 ST_Main_POS_SW_HVS_19 "主正继电器驱动状态 备注：应用层的驱动指令信号";
CM_ SG_ 2332229459 ST_Main_NEG_SW_HVS_19 "主负继电器驱动状态 备注：应用层的驱动指令信号";
CM_ SG_ 2332229459 ST_System_19 "单柜是否允许上高压状态                                 未上高压前：0 为不允许上高压，1为允许上高压。上高压后：0为请求下高压，1为允许正常使用。";
CM_ SG_ 2332229459 ST_CALIBRATION_19 "单柜调试模式反馈                                   P2S调整报文发送（0x01 继电器指令，0x02 均衡指令，0x03 风机指令）信号的反馈状态，0是未接收相关的调试指令，1：接收到相关的调试指令";
CM_ SG_ 2332229459 ST_Insulation_19 "预留";
CM_ SG_ 2332229459 ST_PowerDown_19 "SBMU的供电输出低压电源状态                                                                           当前信号为低压相关的信号，发送的内部接口为：SeBMSM_LvPwrState 。含义为：SBMU低压电源运行状态反馈标志 ";
CM_ SG_ 2332229459 ST_pwr12V_19 "MCU反馈的12V电源pin应答状态";
CM_ SG_ 2332229459 ST_pwr5V_19 "预留";
CM_ SG_ 2332229459 ST_pwr24V_19 "通过MCU反馈的24V电源pin应答状态";
CM_ SG_ 2332229459 ST_pwrStatus_19 "单柜高压状态                                        当前为上高压完成信号：SbPRCC_HvPwrOnFinishFlg
 1,主正继电器的驱动指令为驱动闭合状态，且真实状态为闭合状态                                    2,主负继电器的驱动指令为驱动闭合状态，且真实状态为闭合状态                                     3, 预充继电器驱动指令为断开状态；                      同时满足条件1,2,3后保持1s 后该信号置为高压已上电
";
CM_ SG_ 2332229459 S2A_S2_FullChgFlgFromSBMU_19 "满充标志位";
CM_ SG_ 2332229459 ST_cscStandby_19 "CSC工作状态";
CM_ SG_ 2332229459 ST_OffReasonMsg_19 "主回路断开原因—每个bit代表一个原因，当前仅发送了前16个bit
 具体含义如下：
 Bit0: 高压无效Bit1:驱动短地Bit2:故障禁止上高压 forbid closeBit3:CSC编码中Bit4:概要数据中电压无效Bit5:概要数据温度无Bit6:预留调试模式（未使用）Bit7-Bit9: （未使用）Bit10: 未收到上高压指令Bit11: 故障强制断开继电器（force open）Bit12: 故障延迟断开继电器（normal Open）Bit13-Bit15: （未使用）";
CM_ SG_ 2332229460 CRC_S2A_S2_20 "S2A概要数据2 的CRC";
CM_ SG_ 2332229460 ALIV_ST_SW_HVS_20 "生命信号，0~15循环";
CM_ SG_ 2332229460 ST_PreCharge_SW_HVS_20 "预充继电器驱动状态  备注：应用层的驱动指令信号";
CM_ SG_ 2332229460 ST_Main_POS_SW_HVS_20 "主正继电器驱动状态 备注：应用层的驱动指令信号";
CM_ SG_ 2332229460 ST_Main_NEG_SW_HVS_20 "主负继电器驱动状态 备注：应用层的驱动指令信号";
CM_ SG_ 2332229460 ST_System_20 "单柜是否允许上高压状态                                 未上高压前：0 为不允许上高压，1为允许上高压。上高压后：0为请求下高压，1为允许正常使用。";
CM_ SG_ 2332229460 ST_CALIBRATION_20 "单柜调试模式反馈                                   P2S调整报文发送（0x01 继电器指令，0x02 均衡指令，0x03 风机指令）信号的反馈状态，0是未接收相关的调试指令，1：接收到相关的调试指令";
CM_ SG_ 2332229460 ST_Insulation_20 "预留";
CM_ SG_ 2332229460 ST_PowerDown_20 "SBMU的供电输出低压电源状态                                                                           当前信号为低压相关的信号，发送的内部接口为：SeBMSM_LvPwrState 。含义为：SBMU低压电源运行状态反馈标志 ";
CM_ SG_ 2332229460 ST_pwr12V_20 "MCU反馈的12V电源pin应答状态";
CM_ SG_ 2332229460 ST_pwr5V_20 "预留";
CM_ SG_ 2332229460 ST_pwr24V_20 "通过MCU反馈的24V电源pin应答状态";
CM_ SG_ 2332229460 ST_pwrStatus_20 "单柜高压状态                                        当前为上高压完成信号：SbPRCC_HvPwrOnFinishFlg
 1,主正继电器的驱动指令为驱动闭合状态，且真实状态为闭合状态                                    2,主负继电器的驱动指令为驱动闭合状态，且真实状态为闭合状态                                     3, 预充继电器驱动指令为断开状态；                      同时满足条件1,2,3后保持1s 后该信号置为高压已上电
";
CM_ SG_ 2332229460 S2A_S2_FullChgFlgFromSBMU_20 "满充标志位";
CM_ SG_ 2332229460 ST_cscStandby_20 "CSC工作状态";
CM_ SG_ 2332229460 ST_OffReasonMsg_20 "主回路断开原因—每个bit代表一个原因，当前仅发送了前16个bit
 具体含义如下：
 Bit0: 高压无效Bit1:驱动短地Bit2:故障禁止上高压 forbid closeBit3:CSC编码中Bit4:概要数据中电压无效Bit5:概要数据温度无Bit6:预留调试模式（未使用）Bit7-Bit9: （未使用）Bit10: 未收到上高压指令Bit11: 故障强制断开继电器（force open）Bit12: 故障延迟断开继电器（normal Open）Bit13-Bit15: （未使用）";
CM_ SG_ 2332229461 CRC_S2A_S2_21 "S2A概要数据2 的CRC";
CM_ SG_ 2332229461 ALIV_ST_SW_HVS_21 "生命信号，0~15循环";
CM_ SG_ 2332229461 ST_PreCharge_SW_HVS_21 "预充继电器驱动状态  备注：应用层的驱动指令信号";
CM_ SG_ 2332229461 ST_Main_POS_SW_HVS_21 "主正继电器驱动状态 备注：应用层的驱动指令信号";
CM_ SG_ 2332229461 ST_Main_NEG_SW_HVS_21 "主负继电器驱动状态 备注：应用层的驱动指令信号";
CM_ SG_ 2332229461 ST_System_21 "单柜是否允许上高压状态                                 未上高压前：0 为不允许上高压，1为允许上高压。上高压后：0为请求下高压，1为允许正常使用。";
CM_ SG_ 2332229461 ST_CALIBRATION_21 "单柜调试模式反馈                                   P2S调整报文发送（0x01 继电器指令，0x02 均衡指令，0x03 风机指令）信号的反馈状态，0是未接收相关的调试指令，1：接收到相关的调试指令";
CM_ SG_ 2332229461 ST_Insulation_21 "预留";
CM_ SG_ 2332229461 ST_PowerDown_21 "SBMU的供电输出低压电源状态                                                                           当前信号为低压相关的信号，发送的内部接口为：SeBMSM_LvPwrState 。含义为：SBMU低压电源运行状态反馈标志 ";
CM_ SG_ 2332229461 ST_pwr12V_21 "MCU反馈的12V电源pin应答状态";
CM_ SG_ 2332229461 ST_pwr5V_21 "预留";
CM_ SG_ 2332229461 ST_pwr24V_21 "通过MCU反馈的24V电源pin应答状态";
CM_ SG_ 2332229461 ST_pwrStatus_21 "单柜高压状态                                        当前为上高压完成信号：SbPRCC_HvPwrOnFinishFlg
 1,主正继电器的驱动指令为驱动闭合状态，且真实状态为闭合状态                                    2,主负继电器的驱动指令为驱动闭合状态，且真实状态为闭合状态                                     3, 预充继电器驱动指令为断开状态；                      同时满足条件1,2,3后保持1s 后该信号置为高压已上电
";
CM_ SG_ 2332229461 S2A_S2_FullChgFlgFromSBMU_21 "满充标志位";
CM_ SG_ 2332229461 ST_cscStandby_21 "CSC工作状态";
CM_ SG_ 2332229461 ST_OffReasonMsg_21 "主回路断开原因—每个bit代表一个原因，当前仅发送了前16个bit
 具体含义如下：
 Bit0: 高压无效Bit1:驱动短地Bit2:故障禁止上高压 forbid closeBit3:CSC编码中Bit4:概要数据中电压无效Bit5:概要数据温度无Bit6:预留调试模式（未使用）Bit7-Bit9: （未使用）Bit10: 未收到上高压指令Bit11: 故障强制断开继电器（force open）Bit12: 故障延迟断开继电器（normal Open）Bit13-Bit15: （未使用）";
CM_ SG_ 2332229462 CRC_S2A_S2_22 "S2A概要数据2 的CRC";
CM_ SG_ 2332229462 ALIV_ST_SW_HVS_22 "生命信号，0~15循环";
CM_ SG_ 2332229462 ST_PreCharge_SW_HVS_22 "预充继电器驱动状态  备注：应用层的驱动指令信号";
CM_ SG_ 2332229462 ST_Main_POS_SW_HVS_22 "主正继电器驱动状态 备注：应用层的驱动指令信号";
CM_ SG_ 2332229462 ST_Main_NEG_SW_HVS_22 "主负继电器驱动状态 备注：应用层的驱动指令信号";
CM_ SG_ 2332229462 ST_System_22 "单柜是否允许上高压状态                                 未上高压前：0 为不允许上高压，1为允许上高压。上高压后：0为请求下高压，1为允许正常使用。";
CM_ SG_ 2332229462 ST_CALIBRATION_22 "单柜调试模式反馈                                   P2S调整报文发送（0x01 继电器指令，0x02 均衡指令，0x03 风机指令）信号的反馈状态，0是未接收相关的调试指令，1：接收到相关的调试指令";
CM_ SG_ 2332229462 ST_Insulation_22 "预留";
CM_ SG_ 2332229462 ST_PowerDown_22 "SBMU的供电输出低压电源状态                                                                           当前信号为低压相关的信号，发送的内部接口为：SeBMSM_LvPwrState 。含义为：SBMU低压电源运行状态反馈标志 ";
CM_ SG_ 2332229462 ST_pwr12V_22 "MCU反馈的12V电源pin应答状态";
CM_ SG_ 2332229462 ST_pwr5V_22 "预留";
CM_ SG_ 2332229462 ST_pwr24V_22 "通过MCU反馈的24V电源pin应答状态";
CM_ SG_ 2332229462 ST_pwrStatus_22 "单柜高压状态                                        当前为上高压完成信号：SbPRCC_HvPwrOnFinishFlg
 1,主正继电器的驱动指令为驱动闭合状态，且真实状态为闭合状态                                    2,主负继电器的驱动指令为驱动闭合状态，且真实状态为闭合状态                                     3, 预充继电器驱动指令为断开状态；                      同时满足条件1,2,3后保持1s 后该信号置为高压已上电
";
CM_ SG_ 2332229462 S2A_S2_FullChgFlgFromSBMU_22 "满充标志位";
CM_ SG_ 2332229462 ST_cscStandby_22 "CSC工作状态";
CM_ SG_ 2332229462 ST_OffReasonMsg_22 "主回路断开原因—每个bit代表一个原因，当前仅发送了前16个bit
 具体含义如下：
 Bit0: 高压无效Bit1:驱动短地Bit2:故障禁止上高压 forbid closeBit3:CSC编码中Bit4:概要数据中电压无效Bit5:概要数据温度无Bit6:预留调试模式（未使用）Bit7-Bit9: （未使用）Bit10: 未收到上高压指令Bit11: 故障强制断开继电器（force open）Bit12: 故障延迟断开继电器（normal Open）Bit13-Bit15: （未使用）";
CM_ SG_ 2332229463 CRC_S2A_S2_23 "S2A概要数据2 的CRC";
CM_ SG_ 2332229463 ALIV_ST_SW_HVS_23 "生命信号，0~15循环";
CM_ SG_ 2332229463 ST_PreCharge_SW_HVS_23 "预充继电器驱动状态  备注：应用层的驱动指令信号";
CM_ SG_ 2332229463 ST_Main_POS_SW_HVS_23 "主正继电器驱动状态 备注：应用层的驱动指令信号";
CM_ SG_ 2332229463 ST_Main_NEG_SW_HVS_23 "主负继电器驱动状态 备注：应用层的驱动指令信号";
CM_ SG_ 2332229463 ST_System_23 "单柜是否允许上高压状态                                 未上高压前：0 为不允许上高压，1为允许上高压。上高压后：0为请求下高压，1为允许正常使用。";
CM_ SG_ 2332229463 ST_CALIBRATION_23 "单柜调试模式反馈                                   P2S调整报文发送（0x01 继电器指令，0x02 均衡指令，0x03 风机指令）信号的反馈状态，0是未接收相关的调试指令，1：接收到相关的调试指令";
CM_ SG_ 2332229463 ST_Insulation_23 "预留";
CM_ SG_ 2332229463 ST_PowerDown_23 "SBMU的供电输出低压电源状态                                                                           当前信号为低压相关的信号，发送的内部接口为：SeBMSM_LvPwrState 。含义为：SBMU低压电源运行状态反馈标志 ";
CM_ SG_ 2332229463 ST_pwr12V_23 "MCU反馈的12V电源pin应答状态";
CM_ SG_ 2332229463 ST_pwr5V_23 "预留";
CM_ SG_ 2332229463 ST_pwr24V_23 "通过MCU反馈的24V电源pin应答状态";
CM_ SG_ 2332229463 ST_pwrStatus_23 "单柜高压状态                                        当前为上高压完成信号：SbPRCC_HvPwrOnFinishFlg
 1,主正继电器的驱动指令为驱动闭合状态，且真实状态为闭合状态                                    2,主负继电器的驱动指令为驱动闭合状态，且真实状态为闭合状态                                     3, 预充继电器驱动指令为断开状态；                      同时满足条件1,2,3后保持1s 后该信号置为高压已上电
";
CM_ SG_ 2332229463 S2A_S2_FullChgFlgFromSBMU_23 "满充标志位";
CM_ SG_ 2332229463 ST_cscStandby_23 "CSC工作状态";
CM_ SG_ 2332229463 ST_OffReasonMsg_23 "主回路断开原因—每个bit代表一个原因，当前仅发送了前16个bit
 具体含义如下：
 Bit0: 高压无效Bit1:驱动短地Bit2:故障禁止上高压 forbid closeBit3:CSC编码中Bit4:概要数据中电压无效Bit5:概要数据温度无Bit6:预留调试模式（未使用）Bit7-Bit9: （未使用）Bit10: 未收到上高压指令Bit11: 故障强制断开继电器（force open）Bit12: 故障延迟断开继电器（normal Open）Bit13-Bit15: （未使用）";
CM_ SG_ 2332229464 CRC_S2A_S2_24 "S2A概要数据2 的CRC";
CM_ SG_ 2332229464 ALIV_ST_SW_HVS_24 "生命信号，0~15循环";
CM_ SG_ 2332229464 ST_PreCharge_SW_HVS_24 "预充继电器驱动状态  备注：应用层的驱动指令信号";
CM_ SG_ 2332229464 ST_Main_POS_SW_HVS_24 "主正继电器驱动状态 备注：应用层的驱动指令信号";
CM_ SG_ 2332229464 ST_Main_NEG_SW_HVS_24 "主负继电器驱动状态 备注：应用层的驱动指令信号";
CM_ SG_ 2332229464 ST_System_24 "单柜是否允许上高压状态                                 未上高压前：0 为不允许上高压，1为允许上高压。上高压后：0为请求下高压，1为允许正常使用。";
CM_ SG_ 2332229464 ST_CALIBRATION_24 "单柜调试模式反馈                                   P2S调整报文发送（0x01 继电器指令，0x02 均衡指令，0x03 风机指令）信号的反馈状态，0是未接收相关的调试指令，1：接收到相关的调试指令";
CM_ SG_ 2332229464 ST_Insulation_24 "预留";
CM_ SG_ 2332229464 ST_PowerDown_24 "SBMU的供电输出低压电源状态                                                                           当前信号为低压相关的信号，发送的内部接口为：SeBMSM_LvPwrState 。含义为：SBMU低压电源运行状态反馈标志 ";
CM_ SG_ 2332229464 ST_pwr12V_24 "MCU反馈的12V电源pin应答状态";
CM_ SG_ 2332229464 ST_pwr5V_24 "预留";
CM_ SG_ 2332229464 ST_pwr24V_24 "通过MCU反馈的24V电源pin应答状态";
CM_ SG_ 2332229464 ST_pwrStatus_24 "单柜高压状态                                        当前为上高压完成信号：SbPRCC_HvPwrOnFinishFlg
 1,主正继电器的驱动指令为驱动闭合状态，且真实状态为闭合状态                                    2,主负继电器的驱动指令为驱动闭合状态，且真实状态为闭合状态                                     3, 预充继电器驱动指令为断开状态；                      同时满足条件1,2,3后保持1s 后该信号置为高压已上电
";
CM_ SG_ 2332229464 S2A_S2_FullChgFlgFromSBMU_24 "满充标志位";
CM_ SG_ 2332229464 ST_cscStandby_24 "CSC工作状态";
CM_ SG_ 2332229464 ST_OffReasonMsg_24 "主回路断开原因—每个bit代表一个原因，当前仅发送了前16个bit
 具体含义如下：
 Bit0: 高压无效Bit1:驱动短地Bit2:故障禁止上高压 forbid closeBit3:CSC编码中Bit4:概要数据中电压无效Bit5:概要数据温度无Bit6:预留调试模式（未使用）Bit7-Bit9: （未使用）Bit10: 未收到上高压指令Bit11: 故障强制断开继电器（force open）Bit12: 故障延迟断开继电器（normal Open）Bit13-Bit15: （未使用）";
CM_ SG_ 2332229465 CRC_S2A_S2_25 "S2A概要数据2 的CRC";
CM_ SG_ 2332229465 ALIV_ST_SW_HVS_25 "生命信号，0~15循环";
CM_ SG_ 2332229465 ST_PreCharge_SW_HVS_25 "预充继电器驱动状态  备注：应用层的驱动指令信号";
CM_ SG_ 2332229465 ST_Main_POS_SW_HVS_25 "主正继电器驱动状态 备注：应用层的驱动指令信号";
CM_ SG_ 2332229465 ST_Main_NEG_SW_HVS_25 "主负继电器驱动状态 备注：应用层的驱动指令信号";
CM_ SG_ 2332229465 ST_System_25 "单柜是否允许上高压状态                                 未上高压前：0 为不允许上高压，1为允许上高压。上高压后：0为请求下高压，1为允许正常使用。";
CM_ SG_ 2332229465 ST_CALIBRATION_25 "单柜调试模式反馈                                   P2S调整报文发送（0x01 继电器指令，0x02 均衡指令，0x03 风机指令）信号的反馈状态，0是未接收相关的调试指令，1：接收到相关的调试指令";
CM_ SG_ 2332229465 ST_Insulation_25 "预留";
CM_ SG_ 2332229465 ST_PowerDown_25 "SBMU的供电输出低压电源状态                                                                           当前信号为低压相关的信号，发送的内部接口为：SeBMSM_LvPwrState 。含义为：SBMU低压电源运行状态反馈标志 ";
CM_ SG_ 2332229465 ST_pwr12V_25 "MCU反馈的12V电源pin应答状态";
CM_ SG_ 2332229465 ST_pwr5V_25 "预留";
CM_ SG_ 2332229465 ST_pwr24V_25 "通过MCU反馈的24V电源pin应答状态";
CM_ SG_ 2332229465 ST_pwrStatus_25 "单柜高压状态                                        当前为上高压完成信号：SbPRCC_HvPwrOnFinishFlg
 1,主正继电器的驱动指令为驱动闭合状态，且真实状态为闭合状态                                    2,主负继电器的驱动指令为驱动闭合状态，且真实状态为闭合状态                                     3, 预充继电器驱动指令为断开状态；                      同时满足条件1,2,3后保持1s 后该信号置为高压已上电
";
CM_ SG_ 2332229465 S2A_S2_FullChgFlgFromSBMU_25 "满充标志位";
CM_ SG_ 2332229465 ST_cscStandby_25 "CSC工作状态";
CM_ SG_ 2332229465 ST_OffReasonMsg_25 "主回路断开原因—每个bit代表一个原因，当前仅发送了前16个bit
 具体含义如下：
 Bit0: 高压无效Bit1:驱动短地Bit2:故障禁止上高压 forbid closeBit3:CSC编码中Bit4:概要数据中电压无效Bit5:概要数据温度无Bit6:预留调试模式（未使用）Bit7-Bit9: （未使用）Bit10: 未收到上高压指令Bit11: 故障强制断开继电器（force open）Bit12: 故障延迟断开继电器（normal Open）Bit13-Bit15: （未使用）";
CM_ SG_ 2332229466 CRC_S2A_S2_26 "S2A概要数据2 的CRC";
CM_ SG_ 2332229466 ALIV_ST_SW_HVS_26 "生命信号，0~15循环";
CM_ SG_ 2332229466 ST_PreCharge_SW_HVS_26 "预充继电器驱动状态  备注：应用层的驱动指令信号";
CM_ SG_ 2332229466 ST_Main_POS_SW_HVS_26 "主正继电器驱动状态 备注：应用层的驱动指令信号";
CM_ SG_ 2332229466 ST_Main_NEG_SW_HVS_26 "主负继电器驱动状态 备注：应用层的驱动指令信号";
CM_ SG_ 2332229466 ST_System_26 "单柜是否允许上高压状态                                 未上高压前：0 为不允许上高压，1为允许上高压。上高压后：0为请求下高压，1为允许正常使用。";
CM_ SG_ 2332229466 ST_CALIBRATION_26 "单柜调试模式反馈                                   P2S调整报文发送（0x01 继电器指令，0x02 均衡指令，0x03 风机指令）信号的反馈状态，0是未接收相关的调试指令，1：接收到相关的调试指令";
CM_ SG_ 2332229466 ST_Insulation_26 "预留";
CM_ SG_ 2332229466 ST_PowerDown_26 "SBMU的供电输出低压电源状态                                                                           当前信号为低压相关的信号，发送的内部接口为：SeBMSM_LvPwrState 。含义为：SBMU低压电源运行状态反馈标志 ";
CM_ SG_ 2332229466 ST_pwr12V_26 "MCU反馈的12V电源pin应答状态";
CM_ SG_ 2332229466 ST_pwr5V_26 "预留";
CM_ SG_ 2332229466 ST_pwr24V_26 "通过MCU反馈的24V电源pin应答状态";
CM_ SG_ 2332229466 ST_pwrStatus_26 "单柜高压状态                                        当前为上高压完成信号：SbPRCC_HvPwrOnFinishFlg
 1,主正继电器的驱动指令为驱动闭合状态，且真实状态为闭合状态                                    2,主负继电器的驱动指令为驱动闭合状态，且真实状态为闭合状态                                     3, 预充继电器驱动指令为断开状态；                      同时满足条件1,2,3后保持1s 后该信号置为高压已上电
";
CM_ SG_ 2332229466 S2A_S2_FullChgFlgFromSBMU_26 "满充标志位";
CM_ SG_ 2332229466 ST_cscStandby_26 "CSC工作状态";
CM_ SG_ 2332229466 ST_OffReasonMsg_26 "主回路断开原因—每个bit代表一个原因，当前仅发送了前16个bit
 具体含义如下：
 Bit0: 高压无效Bit1:驱动短地Bit2:故障禁止上高压 forbid closeBit3:CSC编码中Bit4:概要数据中电压无效Bit5:概要数据温度无Bit6:预留调试模式（未使用）Bit7-Bit9: （未使用）Bit10: 未收到上高压指令Bit11: 故障强制断开继电器（force open）Bit12: 故障延迟断开继电器（normal Open）Bit13-Bit15: （未使用）";
CM_ SG_ 2332229467 CRC_S2A_S2_27 "S2A概要数据2 的CRC";
CM_ SG_ 2332229467 ALIV_ST_SW_HVS_27 "生命信号，0~15循环";
CM_ SG_ 2332229467 ST_PreCharge_SW_HVS_27 "预充继电器驱动状态  备注：应用层的驱动指令信号";
CM_ SG_ 2332229467 ST_Main_POS_SW_HVS_27 "主正继电器驱动状态 备注：应用层的驱动指令信号";
CM_ SG_ 2332229467 ST_Main_NEG_SW_HVS_27 "主负继电器驱动状态 备注：应用层的驱动指令信号";
CM_ SG_ 2332229467 ST_System_27 "单柜是否允许上高压状态                                 未上高压前：0 为不允许上高压，1为允许上高压。上高压后：0为请求下高压，1为允许正常使用。";
CM_ SG_ 2332229467 ST_CALIBRATION_27 "单柜调试模式反馈                                   P2S调整报文发送（0x01 继电器指令，0x02 均衡指令，0x03 风机指令）信号的反馈状态，0是未接收相关的调试指令，1：接收到相关的调试指令";
CM_ SG_ 2332229467 ST_Insulation_27 "预留";
CM_ SG_ 2332229467 ST_PowerDown_27 "SBMU的供电输出低压电源状态                                                                           当前信号为低压相关的信号，发送的内部接口为：SeBMSM_LvPwrState 。含义为：SBMU低压电源运行状态反馈标志 ";
CM_ SG_ 2332229467 ST_pwr12V_27 "MCU反馈的12V电源pin应答状态";
CM_ SG_ 2332229467 ST_pwr5V_27 "预留";
CM_ SG_ 2332229467 ST_pwr24V_27 "通过MCU反馈的24V电源pin应答状态";
CM_ SG_ 2332229467 ST_pwrStatus_27 "单柜高压状态                                        当前为上高压完成信号：SbPRCC_HvPwrOnFinishFlg
 1,主正继电器的驱动指令为驱动闭合状态，且真实状态为闭合状态                                    2,主负继电器的驱动指令为驱动闭合状态，且真实状态为闭合状态                                     3, 预充继电器驱动指令为断开状态；                      同时满足条件1,2,3后保持1s 后该信号置为高压已上电
";
CM_ SG_ 2332229467 S2A_S2_FullChgFlgFromSBMU_27 "满充标志位";
CM_ SG_ 2332229467 ST_cscStandby_27 "CSC工作状态";
CM_ SG_ 2332229467 ST_OffReasonMsg_27 "主回路断开原因—每个bit代表一个原因，当前仅发送了前16个bit
 具体含义如下：
 Bit0: 高压无效Bit1:驱动短地Bit2:故障禁止上高压 forbid closeBit3:CSC编码中Bit4:概要数据中电压无效Bit5:概要数据温度无Bit6:预留调试模式（未使用）Bit7-Bit9: （未使用）Bit10: 未收到上高压指令Bit11: 故障强制断开继电器（force open）Bit12: 故障延迟断开继电器（normal Open）Bit13-Bit15: （未使用）";
CM_ SG_ 2332229468 CRC_S2A_S2_28 "S2A概要数据2 的CRC";
CM_ SG_ 2332229468 ALIV_ST_SW_HVS_28 "生命信号，0~15循环";
CM_ SG_ 2332229468 ST_PreCharge_SW_HVS_28 "预充继电器驱动状态  备注：应用层的驱动指令信号";
CM_ SG_ 2332229468 ST_Main_POS_SW_HVS_28 "主正继电器驱动状态 备注：应用层的驱动指令信号";
CM_ SG_ 2332229468 ST_Main_NEG_SW_HVS_28 "主负继电器驱动状态 备注：应用层的驱动指令信号";
CM_ SG_ 2332229468 ST_System_28 "单柜是否允许上高压状态                                 未上高压前：0 为不允许上高压，1为允许上高压。上高压后：0为请求下高压，1为允许正常使用。";
CM_ SG_ 2332229468 ST_CALIBRATION_28 "单柜调试模式反馈                                   P2S调整报文发送（0x01 继电器指令，0x02 均衡指令，0x03 风机指令）信号的反馈状态，0是未接收相关的调试指令，1：接收到相关的调试指令";
CM_ SG_ 2332229468 ST_Insulation_28 "预留";
CM_ SG_ 2332229468 ST_PowerDown_28 "SBMU的供电输出低压电源状态                                                                           当前信号为低压相关的信号，发送的内部接口为：SeBMSM_LvPwrState 。含义为：SBMU低压电源运行状态反馈标志 ";
CM_ SG_ 2332229468 ST_pwr12V_28 "MCU反馈的12V电源pin应答状态";
CM_ SG_ 2332229468 ST_pwr5V_28 "预留";
CM_ SG_ 2332229468 ST_pwr24V_28 "通过MCU反馈的24V电源pin应答状态";
CM_ SG_ 2332229468 ST_pwrStatus_28 "单柜高压状态                                        当前为上高压完成信号：SbPRCC_HvPwrOnFinishFlg
 1,主正继电器的驱动指令为驱动闭合状态，且真实状态为闭合状态                                    2,主负继电器的驱动指令为驱动闭合状态，且真实状态为闭合状态                                     3, 预充继电器驱动指令为断开状态；                      同时满足条件1,2,3后保持1s 后该信号置为高压已上电
";
CM_ SG_ 2332229468 S2A_S2_FullChgFlgFromSBMU_28 "满充标志位";
CM_ SG_ 2332229468 ST_cscStandby_28 "CSC工作状态";
CM_ SG_ 2332229468 ST_OffReasonMsg_28 "主回路断开原因—每个bit代表一个原因，当前仅发送了前16个bit
 具体含义如下：
 Bit0: 高压无效Bit1:驱动短地Bit2:故障禁止上高压 forbid closeBit3:CSC编码中Bit4:概要数据中电压无效Bit5:概要数据温度无Bit6:预留调试模式（未使用）Bit7-Bit9: （未使用）Bit10: 未收到上高压指令Bit11: 故障强制断开继电器（force open）Bit12: 故障延迟断开继电器（normal Open）Bit13-Bit15: （未使用）";
CM_ SG_ 2332229469 CRC_S2A_S2_29 "S2A概要数据2 的CRC";
CM_ SG_ 2332229469 ALIV_ST_SW_HVS_29 "生命信号，0~15循环";
CM_ SG_ 2332229469 ST_PreCharge_SW_HVS_29 "预充继电器驱动状态  备注：应用层的驱动指令信号";
CM_ SG_ 2332229469 ST_Main_POS_SW_HVS_29 "主正继电器驱动状态 备注：应用层的驱动指令信号";
CM_ SG_ 2332229469 ST_Main_NEG_SW_HVS_29 "主负继电器驱动状态 备注：应用层的驱动指令信号";
CM_ SG_ 2332229469 ST_System_29 "单柜是否允许上高压状态                                 未上高压前：0 为不允许上高压，1为允许上高压。上高压后：0为请求下高压，1为允许正常使用。";
CM_ SG_ 2332229469 ST_CALIBRATION_29 "单柜调试模式反馈                                   P2S调整报文发送（0x01 继电器指令，0x02 均衡指令，0x03 风机指令）信号的反馈状态，0是未接收相关的调试指令，1：接收到相关的调试指令";
CM_ SG_ 2332229469 ST_Insulation_29 "预留";
CM_ SG_ 2332229469 ST_PowerDown_29 "SBMU的供电输出低压电源状态                                                                           当前信号为低压相关的信号，发送的内部接口为：SeBMSM_LvPwrState 。含义为：SBMU低压电源运行状态反馈标志 ";
CM_ SG_ 2332229469 ST_pwr12V_29 "MCU反馈的12V电源pin应答状态";
CM_ SG_ 2332229469 ST_pwr5V_29 "预留";
CM_ SG_ 2332229469 ST_pwr24V_29 "通过MCU反馈的24V电源pin应答状态";
CM_ SG_ 2332229469 ST_pwrStatus_29 "单柜高压状态                                        当前为上高压完成信号：SbPRCC_HvPwrOnFinishFlg
 1,主正继电器的驱动指令为驱动闭合状态，且真实状态为闭合状态                                    2,主负继电器的驱动指令为驱动闭合状态，且真实状态为闭合状态                                     3, 预充继电器驱动指令为断开状态；                      同时满足条件1,2,3后保持1s 后该信号置为高压已上电
";
CM_ SG_ 2332229469 S2A_S2_FullChgFlgFromSBMU_29 "满充标志位";
CM_ SG_ 2332229469 ST_cscStandby_29 "CSC工作状态";
CM_ SG_ 2332229469 ST_OffReasonMsg_29 "主回路断开原因—每个bit代表一个原因，当前仅发送了前16个bit
 具体含义如下：
 Bit0: 高压无效Bit1:驱动短地Bit2:故障禁止上高压 forbid closeBit3:CSC编码中Bit4:概要数据中电压无效Bit5:概要数据温度无Bit6:预留调试模式（未使用）Bit7-Bit9: （未使用）Bit10: 未收到上高压指令Bit11: 故障强制断开继电器（force open）Bit12: 故障延迟断开继电器（normal Open）Bit13-Bit15: （未使用）";
VAL_ 2332163905 BAT_standingstatus_01 0 "SBMU未满足静置状态" 85 "SBMU处于静置状态" ;
VAL_ 2332163906 BAT_standingstatus_02 0 "SBMU未满足静置状态" 85 "SBMU处于静置状态" ;
VAL_ 2332163907 BAT_standingstatus_03 0 "SBMU未满足静置状态" 85 "SBMU处于静置状态" ;
VAL_ 2332163908 BAT_standingstatus_04 0 "SBMU未满足静置状态" 85 "SBMU处于静置状态" ;
VAL_ 2332163909 BAT_standingstatus_05 0 "SBMU未满足静置状态" 85 "SBMU处于静置状态" ;
VAL_ 2332163910 BAT_standingstatus_06 0 "SBMU未满足静置状态" 85 "SBMU处于静置状态" ;
VAL_ 2332163911 BAT_standingstatus_07 0 "SBMU未满足静置状态" 85 "SBMU处于静置状态" ;
VAL_ 2332163912 BAT_standingstatus_08 0 "SBMU未满足静置状态" 85 "SBMU处于静置状态" ;
VAL_ 2332163913 BAT_standingstatus_09 0 "SBMU未满足静置状态" 85 "SBMU处于静置状态" ;
VAL_ 2332163914 BAT_standingstatus_10 0 "SBMU未满足静置状态" 85 "SBMU处于静置状态" ;
VAL_ 2332163915 BAT_standingstatus_11 0 "SBMU未满足静置状态" 85 "SBMU处于静置状态" ;
VAL_ 2332163916 BAT_standingstatus_12 0 "SBMU未满足静置状态" 85 "SBMU处于静置状态" ;
VAL_ 2332163917 BAT_standingstatus_13 0 "SBMU未满足静置状态" 85 "SBMU处于静置状态" ;
VAL_ 2332163918 BAT_standingstatus_14 0 "SBMU未满足静置状态" 85 "SBMU处于静置状态" ;
VAL_ 2332163919 BAT_standingstatus_15 0 "SBMU未满足静置状态" 85 "SBMU处于静置状态" ;
VAL_ 2332163920 BAT_standingstatus_16 0 "SBMU未满足静置状态" 85 "SBMU处于静置状态" ;
VAL_ 2332163921 BAT_standingstatus_17 0 "SBMU未满足静置状态" 85 "SBMU处于静置状态" ;
VAL_ 2332163922 BAT_standingstatus_18 0 "SBMU未满足静置状态" 85 "SBMU处于静置状态" ;
VAL_ 2332163923 BAT_standingstatus_19 0 "SBMU未满足静置状态" 85 "SBMU处于静置状态" ;
VAL_ 2332163924 BAT_standingstatus_20 0 "SBMU未满足静置状态" 85 "SBMU处于静置状态" ;
VAL_ 2332163925 BAT_standingstatus_21 0 "SBMU未满足静置状态" 85 "SBMU处于静置状态" ;
VAL_ 2332163926 BAT_standingstatus_22 0 "SBMU未满足静置状态" 85 "SBMU处于静置状态" ;
VAL_ 2332163927 BAT_standingstatus_23 0 "SBMU未满足静置状态" 85 "SBMU处于静置状态" ;
VAL_ 2332163928 BAT_standingstatus_24 0 "SBMU未满足静置状态" 85 "SBMU处于静置状态" ;
VAL_ 2332163929 BAT_standingstatus_25 0 "SBMU未满足静置状态" 85 "SBMU处于静置状态" ;
VAL_ 2332163930 BAT_standingstatus_26 0 "SBMU未满足静置状态" 85 "SBMU处于静置状态" ;
VAL_ 2332163931 BAT_standingstatus_27 0 "SBMU未满足静置状态" 85 "SBMU处于静置状态" ;
VAL_ 2332163932 BAT_standingstatus_28 0 "SBMU未满足静置状态" 85 "SBMU处于静置状态" ;
VAL_ 2332163933 BAT_standingstatus_29 0 "SBMU未满足静置状态" 85 "SBMU处于静置状态" ;
VAL_ 2332163934 BAT_standingstatus_30 0 "SBMU未满足静置状态" 85 "SBMU处于静置状态" ;
VAL_ 2332163935 BAT_standingstatus_31 0 "SBMU未满足静置状态" 85 "SBMU处于静置状态" ;
VAL_ 2332163936 BAT_standingstatus_32 0 "SBMU未满足静置状态" 85 "SBMU处于静置状态" ;
VAL_ 2332163937 BAT_standingstatus_33 0 "SBMU未满足静置状态" 85 "SBMU处于静置状态" ;
VAL_ 2332163938 BAT_standingstatus_34 0 "SBMU未满足静置状态" 85 "SBMU处于静置状态" ;
VAL_ 2332163939 BAT_standingstatus_35 0 "SBMU未满足静置状态" 85 "SBMU处于静置状态" ;
VAL_ 2332163940 BAT_standingstatus_36 0 "SBMU未满足静置状态" 85 "SBMU处于静置状态" ;
VAL_ 2332163941 BAT_standingstatus_37 0 "SBMU未满足静置状态" 85 "SBMU处于静置状态" ;
VAL_ 2332163942 BAT_standingstatus_38 0 "SBMU未满足静置状态" 85 "SBMU处于静置状态" ;
VAL_ 2332163943 BAT_standingstatus_39 0 "SBMU未满足静置状态" 85 "SBMU处于静置状态" ;
VAL_ 2332163944 BAT_standingstatus_40 0 "SBMU未满足静置状态" 85 "SBMU处于静置状态" ;
VAL_ 2332163945 BAT_standingstatus_41 0 "SBMU未满足静置状态" 85 "SBMU处于静置状态" ;
VAL_ 2332163946 BAT_standingstatus_42 0 "SBMU未满足静置状态" 85 "SBMU处于静置状态" ;
VAL_ 2332163947 BAT_standingstatus_43 0 "SBMU未满足静置状态" 85 "SBMU处于静置状态" ;
VAL_ 2332163948 BAT_standingstatus_44 0 "SBMU未满足静置状态" 85 "SBMU处于静置状态" ;
VAL_ 2332163949 BAT_standingstatus_45 0 "SBMU未满足静置状态" 85 "SBMU处于静置状态" ;
VAL_ 2332163950 BAT_standingstatus_46 0 "SBMU未满足静置状态" 85 "SBMU处于静置状态" ;
VAL_ 2332163951 BAT_standingstatus_47 0 "SBMU未满足静置状态" 85 "SBMU处于静置状态" ;
VAL_ 2332163952 BAT_standingstatus_48 0 "SBMU未满足静置状态" 85 "SBMU处于静置状态" ;
VAL_ 2332163953 BAT_standingstatus_49 0 "SBMU未满足静置状态" 85 "SBMU处于静置状态" ;
VAL_ 2332163954 BAT_standingstatus_50 0 "SBMU未满足静置状态" 85 "SBMU处于静置状态" ;
VAL_ 2332163955 BAT_standingstatus_51 0 "SBMU未满足静置状态" 85 "SBMU处于静置状态" ;
VAL_ 2332163956 BAT_standingstatus_52 0 "SBMU未满足静置状态" 85 "SBMU处于静置状态" ;
VAL_ 2332163957 BAT_standingstatus_53 0 "SBMU未满足静置状态" 85 "SBMU处于静置状态" ;
VAL_ 2332163958 BAT_standingstatus_54 0 "SBMU未满足静置状态" 85 "SBMU处于静置状态" ;
VAL_ 2332163959 BAT_standingstatus_55 0 "SBMU未满足静置状态" 85 "SBMU处于静置状态" ;
VAL_ 2332163960 BAT_standingstatus_56 0 "SBMU未满足静置状态" 85 "SBMU处于静置状态" ;
VAL_ 2332163961 BAT_standingstatus_57 0 "SBMU未满足静置状态" 85 "SBMU处于静置状态" ;
VAL_ 2332163962 BAT_standingstatus_58 0 "SBMU未满足静置状态" 85 "SBMU处于静置状态" ;
VAL_ 2332163963 BAT_standingstatus_59 0 "SBMU未满足静置状态" 85 "SBMU处于静置状态" ;
VAL_ 2332163964 BAT_standingstatus_60 0 "SBMU未满足静置状态" 85 "SBMU处于静置状态" ;
VAL_ 2332163965 BAT_standingstatus_61 0 "SBMU未满足静置状态" 85 "SBMU处于静置状态" ;
VAL_ 2332163966 BAT_standingstatus_62 0 "SBMU未满足静置状态" 85 "SBMU处于静置状态" ;
VAL_ 2332163967 BAT_standingstatus_63 0 "SBMU未满足静置状态" 85 "SBMU处于静置状态" ;
VAL_ 2332229441 S2A_S2_FullChgFlgFromSBMU_01 0 "未置位满充" 85 "置位满充" ;
VAL_ 2332229442 S2A_S2_FullChgFlgFromSBMU_02 0 "未置位满充" 85 "置位满充" ;
VAL_ 2332229443 S2A_S2_FullChgFlgFromSBMU_03 0 "未置位满充" 85 "置位满充" ;
VAL_ 2332229444 S2A_S2_FullChgFlgFromSBMU_04 0 "未置位满充" 85 "置位满充" ;
VAL_ 2332229445 S2A_S2_FullChgFlgFromSBMU_05 0 "未置位满充" 85 "置位满充" ;
VAL_ 2332229446 S2A_S2_FullChgFlgFromSBMU_06 0 "未置位满充" 85 "置位满充" ;
VAL_ 2332229447 S2A_S2_FullChgFlgFromSBMU_07 0 "未置位满充" 85 "置位满充" ;
VAL_ 2332229448 S2A_S2_FullChgFlgFromSBMU_08 0 "未置位满充" 85 "置位满充" ;
VAL_ 2332229449 S2A_S2_FullChgFlgFromSBMU_09 0 "未置位满充" 85 "置位满充" ;
VAL_ 2332229450 S2A_S2_FullChgFlgFromSBMU_10 0 "未置位满充" 85 "置位满充" ;
VAL_ 2332229451 S2A_S2_FullChgFlgFromSBMU_11 0 "未置位满充" 85 "置位满充" ;
VAL_ 2332229452 S2A_S2_FullChgFlgFromSBMU_12 0 "未置位满充" 85 "置位满充" ;
VAL_ 2332229453 S2A_S2_FullChgFlgFromSBMU_13 0 "未置位满充" 85 "置位满充" ;
VAL_ 2332229454 S2A_S2_FullChgFlgFromSBMU_14 0 "未置位满充" 85 "置位满充" ;
VAL_ 2332229455 S2A_S2_FullChgFlgFromSBMU_15 0 "未置位满充" 85 "置位满充" ;
VAL_ 2332229456 S2A_S2_FullChgFlgFromSBMU_16 0 "未置位满充" 85 "置位满充" ;
VAL_ 2332229457 S2A_S2_FullChgFlgFromSBMU_17 0 "未置位满充" 85 "置位满充" ;
VAL_ 2332229458 S2A_S2_FullChgFlgFromSBMU_18 0 "未置位满充" 85 "置位满充" ;
VAL_ 2332229459 S2A_S2_FullChgFlgFromSBMU_19 0 "未置位满充" 85 "置位满充" ;
VAL_ 2332229460 S2A_S2_FullChgFlgFromSBMU_20 0 "未置位满充" 85 "置位满充" ;
VAL_ 2332229461 S2A_S2_FullChgFlgFromSBMU_21 0 "未置位满充" 85 "置位满充" ;
VAL_ 2332229462 S2A_S2_FullChgFlgFromSBMU_22 0 "未置位满充" 85 "置位满充" ;
VAL_ 2332229463 S2A_S2_FullChgFlgFromSBMU_23 0 "未置位满充" 85 "置位满充" ;
VAL_ 2332229464 S2A_S2_FullChgFlgFromSBMU_24 0 "未置位满充" 85 "置位满充" ;
VAL_ 2332229465 S2A_S2_FullChgFlgFromSBMU_25 0 "未置位满充" 85 "置位满充" ;
VAL_ 2332229466 S2A_S2_FullChgFlgFromSBMU_26 0 "未置位满充" 85 "置位满充" ;
VAL_ 2332229467 S2A_S2_FullChgFlgFromSBMU_27 0 "未置位满充" 85 "置位满充" ;
VAL_ 2332229468 S2A_S2_FullChgFlgFromSBMU_28 0 "未置位满充" 85 "置位满充" ;
VAL_ 2332229469 S2A_S2_FullChgFlgFromSBMU_29 0 "未置位满充" 85 "置位满充" ;
VERSION ""

NS_ :

BS_:

BU_: MBMU PC SBMU IMM ETH DCDC LEMS

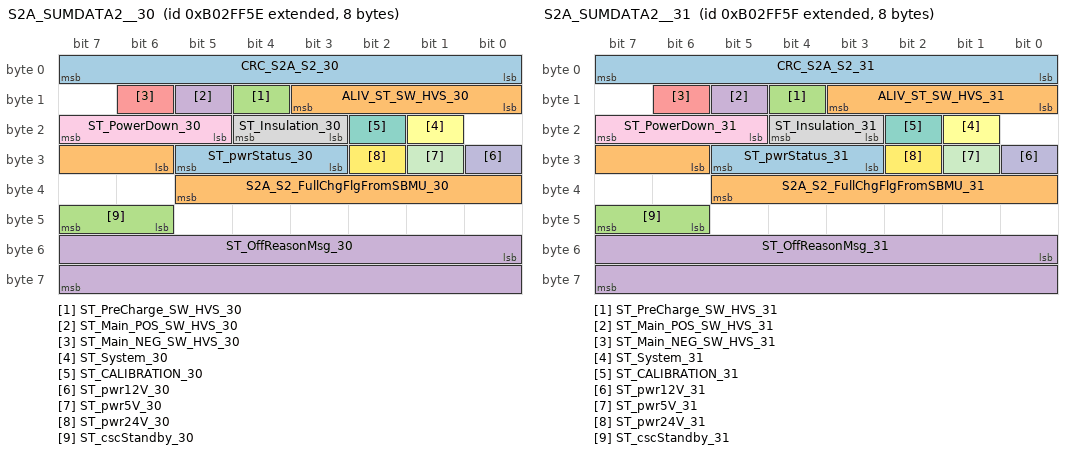
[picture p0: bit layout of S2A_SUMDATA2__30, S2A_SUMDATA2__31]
BO_ 2332229470 S2A_SUMDATA2__30: 8 SBMU
 SG_ CRC_S2A_S2_30 : 0|8@1+ (1,0) [0|255] ""  MBMU,PC
 SG_ ALIV_ST_SW_HVS_30 : 8|4@1+ (1,0) [0|15] ""  MBMU,PC
 SG_ ST_PreCharge_SW_HVS_30 : 12|1@1+ (1,0) [0|1] ""  MBMU,PC
 SG_ ST_Main_POS_SW_HVS_30 : 13|1@1+ (1,0) [0|1] ""  MBMU,PC
 SG_ ST_Main_NEG_SW_HVS_30 : 14|1@1+ (1,0) [0|1] ""  MBMU,PC
 SG_ ST_System_30 : 17|1@1+ (1,0) [0|1] ""  MBMU,PC
 SG_ ST_CALIBRATION_30 : 18|1@1+ (1,0) [0|1] ""  MBMU,PC
 SG_ ST_Insulation_30 : 19|2@1+ (1,0) [0|3] ""  MBMU,PC
 SG_ ST_PowerDown_30 : 21|3@1+ (1,0) [0|7] ""  MBMU,PC
 SG_ ST_pwr12V_30 : 24|1@1+ (1,0) [0|1] ""  MBMU,PC
 SG_ ST_pwr5V_30 : 25|1@1+ (1,0) [0|1] ""  MBMU,PC
 SG_ ST_pwr24V_30 : 26|1@1+ (1,0) [0|1] ""  MBMU,PC
 SG_ ST_pwrStatus_30 : 27|3@1+ (1,0) [0|7] ""  MBMU,PC
 SG_ S2A_S2_FullChgFlgFromSBMU_30 : 30|8@1+ (1,0) [0|255] ""  MBMU,PC
 SG_ ST_cscStandby_30 : 46|2@1+ (1,0) [0|3] ""  MBMU,PC
 SG_ ST_OffReasonMsg_30 : 48|16@1+ (1,0) [0|65535] ""  MBMU,PC

BO_ 2332229471 S2A_SUMDATA2__31: 8 SBMU
 SG_ CRC_S2A_S2_31 : 0|8@1+ (1,0) [0|255] ""  MBMU,PC
 SG_ ALIV_ST_SW_HVS_31 : 8|4@1+ (1,0) [0|15] ""  MBMU,PC
 SG_ ST_PreCharge_SW_HVS_31 : 12|1@1+ (1,0) [0|1] ""  MBMU,PC
 SG_ ST_Main_POS_SW_HVS_31 : 13|1@1+ (1,0) [0|1] ""  MBMU,PC
 SG_ ST_Main_NEG_SW_HVS_31 : 14|1@1+ (1,0) [0|1] ""  MBMU,PC
 SG_ ST_System_31 : 17|1@1+ (1,0) [0|1] ""  MBMU,PC
 SG_ ST_CALIBRATION_31 : 18|1@1+ (1,0) [0|1] ""  MBMU,PC
 SG_ ST_Insulation_31 : 19|2@1+ (1,0) [0|3] ""  MBMU,PC
 SG_ ST_PowerDown_31 : 21|3@1+ (1,0) [0|7] ""  MBMU,PC
 SG_ ST_pwr12V_31 : 24|1@1+ (1,0) [0|1] ""  MBMU,PC
 SG_ ST_pwr5V_31 : 25|1@1+ (1,0) [0|1] ""  MBMU,PC
 SG_ ST_pwr24V_31 : 26|1@1+ (1,0) [0|1] ""  MBMU,PC
 SG_ ST_pwrStatus_31 : 27|3@1+ (1,0) [0|7] ""  MBMU,PC
 SG_ S2A_S2_FullChgFlgFromSBMU_31 : 30|8@1+ (1,0) [0|255] ""  MBMU,PC
 SG_ ST_cscStandby_31 : 46|2@1+ (1,0) [0|3] ""  MBMU,PC
 SG_ ST_OffReasonMsg_31 : 48|16@1+ (1,0) [0|65535] ""  MBMU,PC

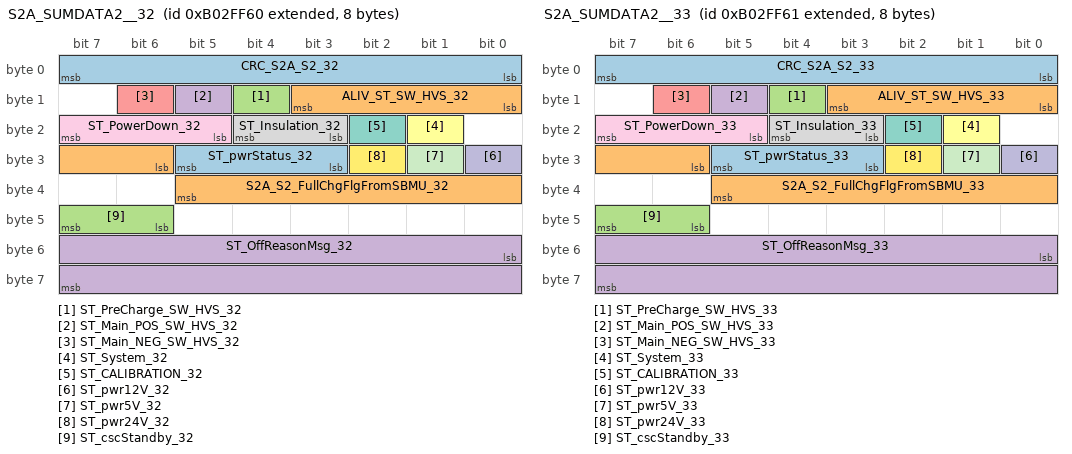
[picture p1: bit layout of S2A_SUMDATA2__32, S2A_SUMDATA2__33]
BO_ 2332229472 S2A_SUMDATA2__32: 8 SBMU
 SG_ CRC_S2A_S2_32 : 0|8@1+ (1,0) [0|255] ""  MBMU,PC
 SG_ ALIV_ST_SW_HVS_32 : 8|4@1+ (1,0) [0|15] ""  MBMU,PC
 SG_ ST_PreCharge_SW_HVS_32 : 12|1@1+ (1,0) [0|1] ""  MBMU,PC
 SG_ ST_Main_POS_SW_HVS_32 : 13|1@1+ (1,0) [0|1] ""  MBMU,PC
 SG_ ST_Main_NEG_SW_HVS_32 : 14|1@1+ (1,0) [0|1] ""  MBMU,PC
 SG_ ST_System_32 : 17|1@1+ (1,0) [0|1] ""  MBMU,PC
 SG_ ST_CALIBRATION_32 : 18|1@1+ (1,0) [0|1] ""  MBMU,PC
 SG_ ST_Insulation_32 : 19|2@1+ (1,0) [0|3] ""  MBMU,PC
 SG_ ST_PowerDown_32 : 21|3@1+ (1,0) [0|7] ""  MBMU,PC
 SG_ ST_pwr12V_32 : 24|1@1+ (1,0) [0|1] ""  MBMU,PC
 SG_ ST_pwr5V_32 : 25|1@1+ (1,0) [0|1] ""  MBMU,PC
 SG_ ST_pwr24V_32 : 26|1@1+ (1,0) [0|1] ""  MBMU,PC
 SG_ ST_pwrStatus_32 : 27|3@1+ (1,0) [0|7] ""  MBMU,PC
 SG_ S2A_S2_FullChgFlgFromSBMU_32 : 30|8@1+ (1,0) [0|255] ""  MBMU,PC
 SG_ ST_cscStandby_32 : 46|2@1+ (1,0) [0|3] ""  MBMU,PC
 SG_ ST_OffReasonMsg_32 : 48|16@1+ (1,0) [0|65535] ""  MBMU,PC

BO_ 2332229473 S2A_SUMDATA2__33: 8 SBMU
 SG_ CRC_S2A_S2_33 : 0|8@1+ (1,0) [0|255] ""  MBMU,PC
 SG_ ALIV_ST_SW_HVS_33 : 8|4@1+ (1,0) [0|15] ""  MBMU,PC
 SG_ ST_PreCharge_SW_HVS_33 : 12|1@1+ (1,0) [0|1] ""  MBMU,PC
 SG_ ST_Main_POS_SW_HVS_33 : 13|1@1+ (1,0) [0|1] ""  MBMU,PC
 SG_ ST_Main_NEG_SW_HVS_33 : 14|1@1+ (1,0) [0|1] ""  MBMU,PC
 SG_ ST_System_33 : 17|1@1+ (1,0) [0|1] ""  MBMU,PC
 SG_ ST_CALIBRATION_33 : 18|1@1+ (1,0) [0|1] ""  MBMU,PC
 SG_ ST_Insulation_33 : 19|2@1+ (1,0) [0|3] ""  MBMU,PC
 SG_ ST_PowerDown_33 : 21|3@1+ (1,0) [0|7] ""  MBMU,PC
 SG_ ST_pwr12V_33 : 24|1@1+ (1,0) [0|1] ""  MBMU,PC
 SG_ ST_pwr5V_33 : 25|1@1+ (1,0) [0|1] ""  MBMU,PC
 SG_ ST_pwr24V_33 : 26|1@1+ (1,0) [0|1] ""  MBMU,PC
 SG_ ST_pwrStatus_33 : 27|3@1+ (1,0) [0|7] ""  MBMU,PC
 SG_ S2A_S2_FullChgFlgFromSBMU_33 : 30|8@1+ (1,0) [0|255] ""  MBMU,PC
 SG_ ST_cscStandby_33 : 46|2@1+ (1,0) [0|3] ""  MBMU,PC
 SG_ ST_OffReasonMsg_33 : 48|16@1+ (1,0) [0|65535] ""  MBMU,PC

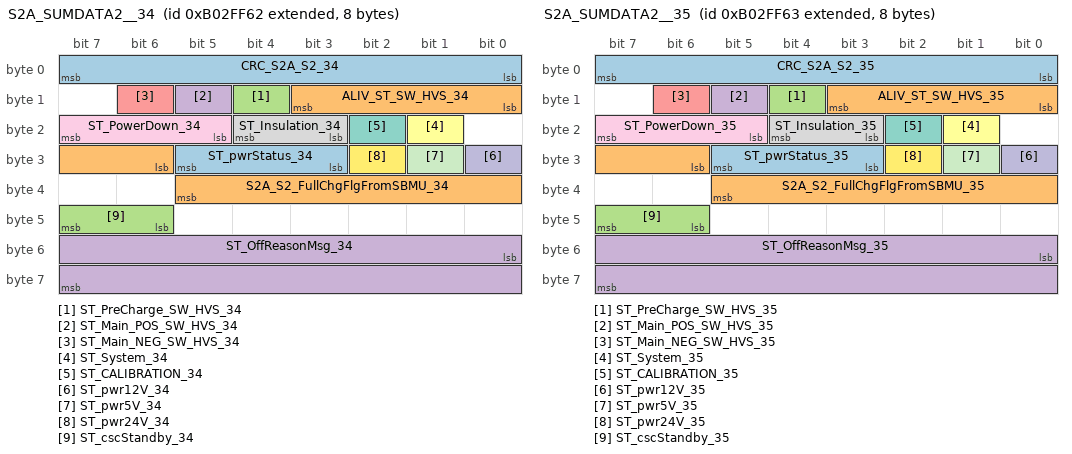
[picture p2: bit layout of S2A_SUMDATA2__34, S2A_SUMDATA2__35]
BO_ 2332229474 S2A_SUMDATA2__34: 8 SBMU
 SG_ CRC_S2A_S2_34 : 0|8@1+ (1,0) [0|255] ""  MBMU,PC
 SG_ ALIV_ST_SW_HVS_34 : 8|4@1+ (1,0) [0|15] ""  MBMU,PC
 SG_ ST_PreCharge_SW_HVS_34 : 12|1@1+ (1,0) [0|1] ""  MBMU,PC
 SG_ ST_Main_POS_SW_HVS_34 : 13|1@1+ (1,0) [0|1] ""  MBMU,PC
 SG_ ST_Main_NEG_SW_HVS_34 : 14|1@1+ (1,0) [0|1] ""  MBMU,PC
 SG_ ST_System_34 : 17|1@1+ (1,0) [0|1] ""  MBMU,PC
 SG_ ST_CALIBRATION_34 : 18|1@1+ (1,0) [0|1] ""  MBMU,PC
 SG_ ST_Insulation_34 : 19|2@1+ (1,0) [0|3] ""  MBMU,PC
 SG_ ST_PowerDown_34 : 21|3@1+ (1,0) [0|7] ""  MBMU,PC
 SG_ ST_pwr12V_34 : 24|1@1+ (1,0) [0|1] ""  MBMU,PC
 SG_ ST_pwr5V_34 : 25|1@1+ (1,0) [0|1] ""  MBMU,PC
 SG_ ST_pwr24V_34 : 26|1@1+ (1,0) [0|1] ""  MBMU,PC
 SG_ ST_pwrStatus_34 : 27|3@1+ (1,0) [0|7] ""  MBMU,PC
 SG_ S2A_S2_FullChgFlgFromSBMU_34 : 30|8@1+ (1,0) [0|255] ""  MBMU,PC
 SG_ ST_cscStandby_34 : 46|2@1+ (1,0) [0|3] ""  MBMU,PC
 SG_ ST_OffReasonMsg_34 : 48|16@1+ (1,0) [0|65535] ""  MBMU,PC

BO_ 2332229475 S2A_SUMDATA2__35: 8 SBMU
 SG_ CRC_S2A_S2_35 : 0|8@1+ (1,0) [0|255] ""  MBMU,PC
 SG_ ALIV_ST_SW_HVS_35 : 8|4@1+ (1,0) [0|15] ""  MBMU,PC
 SG_ ST_PreCharge_SW_HVS_35 : 12|1@1+ (1,0) [0|1] ""  MBMU,PC
 SG_ ST_Main_POS_SW_HVS_35 : 13|1@1+ (1,0) [0|1] ""  MBMU,PC
 SG_ ST_Main_NEG_SW_HVS_35 : 14|1@1+ (1,0) [0|1] ""  MBMU,PC
 SG_ ST_System_35 : 17|1@1+ (1,0) [0|1] ""  MBMU,PC
 SG_ ST_CALIBRATION_35 : 18|1@1+ (1,0) [0|1] ""  MBMU,PC
 SG_ ST_Insulation_35 : 19|2@1+ (1,0) [0|3] ""  MBMU,PC
 SG_ ST_PowerDown_35 : 21|3@1+ (1,0) [0|7] ""  MBMU,PC
 SG_ ST_pwr12V_35 : 24|1@1+ (1,0) [0|1] ""  MBMU,PC
 SG_ ST_pwr5V_35 : 25|1@1+ (1,0) [0|1] ""  MBMU,PC
 SG_ ST_pwr24V_35 : 26|1@1+ (1,0) [0|1] ""  MBMU,PC
 SG_ ST_pwrStatus_35 : 27|3@1+ (1,0) [0|7] ""  MBMU,PC
 SG_ S2A_S2_FullChgFlgFromSBMU_35 : 30|8@1+ (1,0) [0|255] ""  MBMU,PC
 SG_ ST_cscStandby_35 : 46|2@1+ (1,0) [0|3] ""  MBMU,PC
 SG_ ST_OffReasonMsg_35 : 48|16@1+ (1,0) [0|65535] ""  MBMU,PC

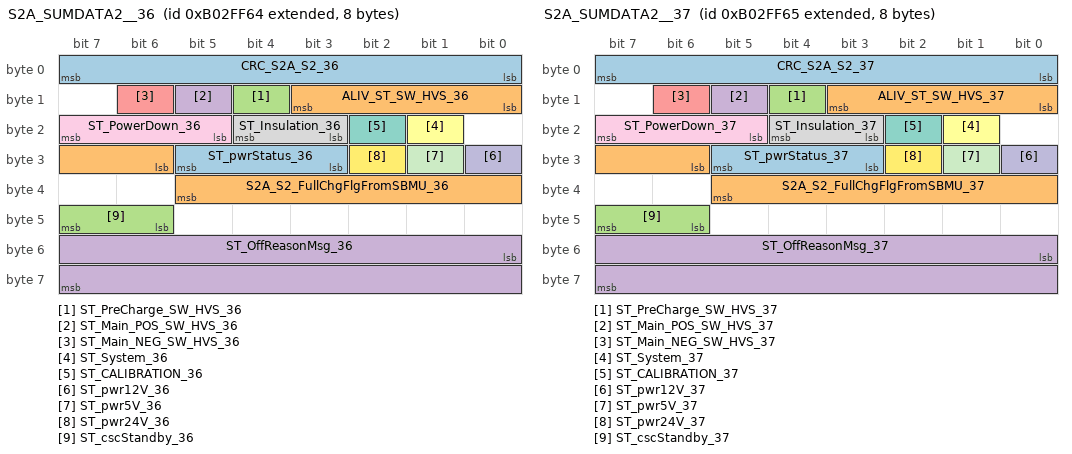
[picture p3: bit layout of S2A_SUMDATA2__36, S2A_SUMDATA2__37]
BO_ 2332229476 S2A_SUMDATA2__36: 8 SBMU
 SG_ CRC_S2A_S2_36 : 0|8@1+ (1,0) [0|255] ""  MBMU,PC
 SG_ ALIV_ST_SW_HVS_36 : 8|4@1+ (1,0) [0|15] ""  MBMU,PC
 SG_ ST_PreCharge_SW_HVS_36 : 12|1@1+ (1,0) [0|1] ""  MBMU,PC
 SG_ ST_Main_POS_SW_HVS_36 : 13|1@1+ (1,0) [0|1] ""  MBMU,PC
 SG_ ST_Main_NEG_SW_HVS_36 : 14|1@1+ (1,0) [0|1] ""  MBMU,PC
 SG_ ST_System_36 : 17|1@1+ (1,0) [0|1] ""  MBMU,PC
 SG_ ST_CALIBRATION_36 : 18|1@1+ (1,0) [0|1] ""  MBMU,PC
 SG_ ST_Insulation_36 : 19|2@1+ (1,0) [0|3] ""  MBMU,PC
 SG_ ST_PowerDown_36 : 21|3@1+ (1,0) [0|7] ""  MBMU,PC
 SG_ ST_pwr12V_36 : 24|1@1+ (1,0) [0|1] ""  MBMU,PC
 SG_ ST_pwr5V_36 : 25|1@1+ (1,0) [0|1] ""  MBMU,PC
 SG_ ST_pwr24V_36 : 26|1@1+ (1,0) [0|1] ""  MBMU,PC
 SG_ ST_pwrStatus_36 : 27|3@1+ (1,0) [0|7] ""  MBMU,PC
 SG_ S2A_S2_FullChgFlgFromSBMU_36 : 30|8@1+ (1,0) [0|255] ""  MBMU,PC
 SG_ ST_cscStandby_36 : 46|2@1+ (1,0) [0|3] ""  MBMU,PC
 SG_ ST_OffReasonMsg_36 : 48|16@1+ (1,0) [0|65535] ""  MBMU,PC

BO_ 2332229477 S2A_SUMDATA2__37: 8 SBMU
 SG_ CRC_S2A_S2_37 : 0|8@1+ (1,0) [0|255] ""  MBMU,PC
 SG_ ALIV_ST_SW_HVS_37 : 8|4@1+ (1,0) [0|15] ""  MBMU,PC
 SG_ ST_PreCharge_SW_HVS_37 : 12|1@1+ (1,0) [0|1] ""  MBMU,PC
 SG_ ST_Main_POS_SW_HVS_37 : 13|1@1+ (1,0) [0|1] ""  MBMU,PC
 SG_ ST_Main_NEG_SW_HVS_37 : 14|1@1+ (1,0) [0|1] ""  MBMU,PC
 SG_ ST_System_37 : 17|1@1+ (1,0) [0|1] ""  MBMU,PC
 SG_ ST_CALIBRATION_37 : 18|1@1+ (1,0) [0|1] ""  MBMU,PC
 SG_ ST_Insulation_37 : 19|2@1+ (1,0) [0|3] ""  MBMU,PC
 SG_ ST_PowerDown_37 : 21|3@1+ (1,0) [0|7] ""  MBMU,PC
 SG_ ST_pwr12V_37 : 24|1@1+ (1,0) [0|1] ""  MBMU,PC
 SG_ ST_pwr5V_37 : 25|1@1+ (1,0) [0|1] ""  MBMU,PC
 SG_ ST_pwr24V_37 : 26|1@1+ (1,0) [0|1] ""  MBMU,PC
 SG_ ST_pwrStatus_37 : 27|3@1+ (1,0) [0|7] ""  MBMU,PC
 SG_ S2A_S2_FullChgFlgFromSBMU_37 : 30|8@1+ (1,0) [0|255] ""  MBMU,PC
 SG_ ST_cscStandby_37 : 46|2@1+ (1,0) [0|3] ""  MBMU,PC
 SG_ ST_OffReasonMsg_37 : 48|16@1+ (1,0) [0|65535] ""  MBMU,PC

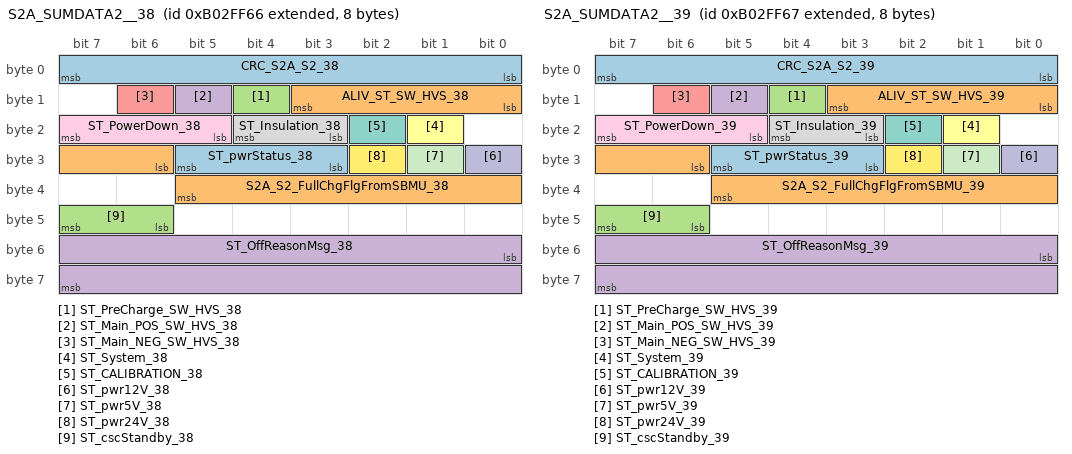
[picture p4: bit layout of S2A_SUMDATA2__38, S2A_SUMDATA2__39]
BO_ 2332229478 S2A_SUMDATA2__38: 8 SBMU
 SG_ CRC_S2A_S2_38 : 0|8@1+ (1,0) [0|255] ""  MBMU,PC
 SG_ ALIV_ST_SW_HVS_38 : 8|4@1+ (1,0) [0|15] ""  MBMU,PC
 SG_ ST_PreCharge_SW_HVS_38 : 12|1@1+ (1,0) [0|1] ""  MBMU,PC
 SG_ ST_Main_POS_SW_HVS_38 : 13|1@1+ (1,0) [0|1] ""  MBMU,PC
 SG_ ST_Main_NEG_SW_HVS_38 : 14|1@1+ (1,0) [0|1] ""  MBMU,PC
 SG_ ST_System_38 : 17|1@1+ (1,0) [0|1] ""  MBMU,PC
 SG_ ST_CALIBRATION_38 : 18|1@1+ (1,0) [0|1] ""  MBMU,PC
 SG_ ST_Insulation_38 : 19|2@1+ (1,0) [0|3] ""  MBMU,PC
 SG_ ST_PowerDown_38 : 21|3@1+ (1,0) [0|7] ""  MBMU,PC
 SG_ ST_pwr12V_38 : 24|1@1+ (1,0) [0|1] ""  MBMU,PC
 SG_ ST_pwr5V_38 : 25|1@1+ (1,0) [0|1] ""  MBMU,PC
 SG_ ST_pwr24V_38 : 26|1@1+ (1,0) [0|1] ""  MBMU,PC
 SG_ ST_pwrStatus_38 : 27|3@1+ (1,0) [0|7] ""  MBMU,PC
 SG_ S2A_S2_FullChgFlgFromSBMU_38 : 30|8@1+ (1,0) [0|255] ""  MBMU,PC
 SG_ ST_cscStandby_38 : 46|2@1+ (1,0) [0|3] ""  MBMU,PC
 SG_ ST_OffReasonMsg_38 : 48|16@1+ (1,0) [0|65535] ""  MBMU,PC

BO_ 2332229479 S2A_SUMDATA2__39: 8 SBMU
 SG_ CRC_S2A_S2_39 : 0|8@1+ (1,0) [0|255] ""  MBMU,PC
 SG_ ALIV_ST_SW_HVS_39 : 8|4@1+ (1,0) [0|15] ""  MBMU,PC
 SG_ ST_PreCharge_SW_HVS_39 : 12|1@1+ (1,0) [0|1] ""  MBMU,PC
 SG_ ST_Main_POS_SW_HVS_39 : 13|1@1+ (1,0) [0|1] ""  MBMU,PC
 SG_ ST_Main_NEG_SW_HVS_39 : 14|1@1+ (1,0) [0|1] ""  MBMU,PC
 SG_ ST_System_39 : 17|1@1+ (1,0) [0|1] ""  MBMU,PC
 SG_ ST_CALIBRATION_39 : 18|1@1+ (1,0) [0|1] ""  MBMU,PC
 SG_ ST_Insulation_39 : 19|2@1+ (1,0) [0|3] ""  MBMU,PC
 SG_ ST_PowerDown_39 : 21|3@1+ (1,0) [0|7] ""  MBMU,PC
 SG_ ST_pwr12V_39 : 24|1@1+ (1,0) [0|1] ""  MBMU,PC
 SG_ ST_pwr5V_39 : 25|1@1+ (1,0) [0|1] ""  MBMU,PC
 SG_ ST_pwr24V_39 : 26|1@1+ (1,0) [0|1] ""  MBMU,PC
 SG_ ST_pwrStatus_39 : 27|3@1+ (1,0) [0|7] ""  MBMU,PC
 SG_ S2A_S2_FullChgFlgFromSBMU_39 : 30|8@1+ (1,0) [0|255] ""  MBMU,PC
 SG_ ST_cscStandby_39 : 46|2@1+ (1,0) [0|3] ""  MBMU,PC
 SG_ ST_OffReasonMsg_39 : 48|16@1+ (1,0) [0|65535] ""  MBMU,PC

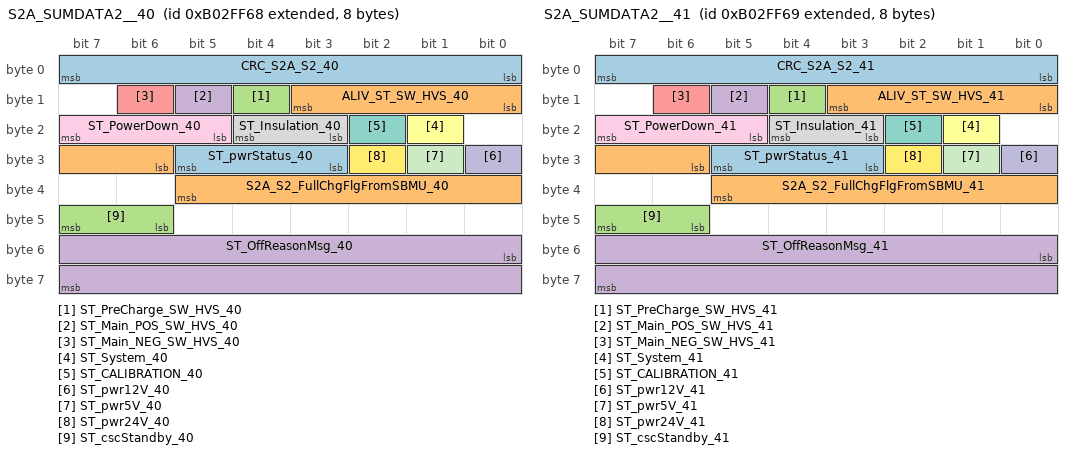
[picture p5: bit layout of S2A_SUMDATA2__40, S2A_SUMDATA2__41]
BO_ 2332229480 S2A_SUMDATA2__40: 8 SBMU
 SG_ CRC_S2A_S2_40 : 0|8@1+ (1,0) [0|255] ""  MBMU,PC
 SG_ ALIV_ST_SW_HVS_40 : 8|4@1+ (1,0) [0|15] ""  MBMU,PC
 SG_ ST_PreCharge_SW_HVS_40 : 12|1@1+ (1,0) [0|1] ""  MBMU,PC
 SG_ ST_Main_POS_SW_HVS_40 : 13|1@1+ (1,0) [0|1] ""  MBMU,PC
 SG_ ST_Main_NEG_SW_HVS_40 : 14|1@1+ (1,0) [0|1] ""  MBMU,PC
 SG_ ST_System_40 : 17|1@1+ (1,0) [0|1] ""  MBMU,PC
 SG_ ST_CALIBRATION_40 : 18|1@1+ (1,0) [0|1] ""  MBMU,PC
 SG_ ST_Insulation_40 : 19|2@1+ (1,0) [0|3] ""  MBMU,PC
 SG_ ST_PowerDown_40 : 21|3@1+ (1,0) [0|7] ""  MBMU,PC
 SG_ ST_pwr12V_40 : 24|1@1+ (1,0) [0|1] ""  MBMU,PC
 SG_ ST_pwr5V_40 : 25|1@1+ (1,0) [0|1] ""  MBMU,PC
 SG_ ST_pwr24V_40 : 26|1@1+ (1,0) [0|1] ""  MBMU,PC
 SG_ ST_pwrStatus_40 : 27|3@1+ (1,0) [0|7] ""  MBMU,PC
 SG_ S2A_S2_FullChgFlgFromSBMU_40 : 30|8@1+ (1,0) [0|255] ""  MBMU,PC
 SG_ ST_cscStandby_40 : 46|2@1+ (1,0) [0|3] ""  MBMU,PC
 SG_ ST_OffReasonMsg_40 : 48|16@1+ (1,0) [0|65535] ""  MBMU,PC

BO_ 2332229481 S2A_SUMDATA2__41: 8 SBMU
 SG_ CRC_S2A_S2_41 : 0|8@1+ (1,0) [0|255] ""  MBMU,PC
 SG_ ALIV_ST_SW_HVS_41 : 8|4@1+ (1,0) [0|15] ""  MBMU,PC
 SG_ ST_PreCharge_SW_HVS_41 : 12|1@1+ (1,0) [0|1] ""  MBMU,PC
 SG_ ST_Main_POS_SW_HVS_41 : 13|1@1+ (1,0) [0|1] ""  MBMU,PC
 SG_ ST_Main_NEG_SW_HVS_41 : 14|1@1+ (1,0) [0|1] ""  MBMU,PC
 SG_ ST_System_41 : 17|1@1+ (1,0) [0|1] ""  MBMU,PC
 SG_ ST_CALIBRATION_41 : 18|1@1+ (1,0) [0|1] ""  MBMU,PC
 SG_ ST_Insulation_41 : 19|2@1+ (1,0) [0|3] ""  MBMU,PC
 SG_ ST_PowerDown_41 : 21|3@1+ (1,0) [0|7] ""  MBMU,PC
 SG_ ST_pwr12V_41 : 24|1@1+ (1,0) [0|1] ""  MBMU,PC
 SG_ ST_pwr5V_41 : 25|1@1+ (1,0) [0|1] ""  MBMU,PC
 SG_ ST_pwr24V_41 : 26|1@1+ (1,0) [0|1] ""  MBMU,PC
 SG_ ST_pwrStatus_41 : 27|3@1+ (1,0) [0|7] ""  MBMU,PC
 SG_ S2A_S2_FullChgFlgFromSBMU_41 : 30|8@1+ (1,0) [0|255] ""  MBMU,PC
 SG_ ST_cscStandby_41 : 46|2@1+ (1,0) [0|3] ""  MBMU,PC
 SG_ ST_OffReasonMsg_41 : 48|16@1+ (1,0) [0|65535] ""  MBMU,PC

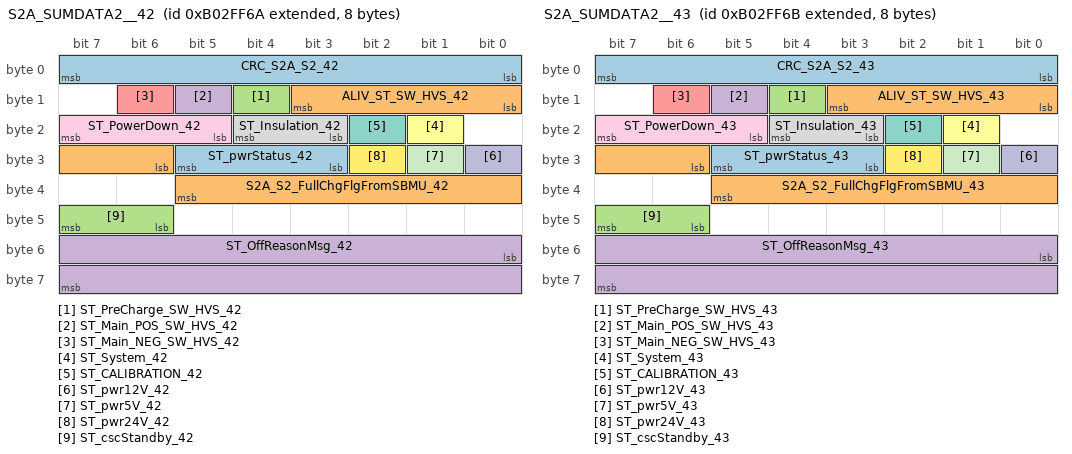
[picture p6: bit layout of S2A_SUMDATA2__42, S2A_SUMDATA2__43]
BO_ 2332229482 S2A_SUMDATA2__42: 8 SBMU
 SG_ CRC_S2A_S2_42 : 0|8@1+ (1,0) [0|255] ""  MBMU,PC
 SG_ ALIV_ST_SW_HVS_42 : 8|4@1+ (1,0) [0|15] ""  MBMU,PC
 SG_ ST_PreCharge_SW_HVS_42 : 12|1@1+ (1,0) [0|1] ""  MBMU,PC
 SG_ ST_Main_POS_SW_HVS_42 : 13|1@1+ (1,0) [0|1] ""  MBMU,PC
 SG_ ST_Main_NEG_SW_HVS_42 : 14|1@1+ (1,0) [0|1] ""  MBMU,PC
 SG_ ST_System_42 : 17|1@1+ (1,0) [0|1] ""  MBMU,PC
 SG_ ST_CALIBRATION_42 : 18|1@1+ (1,0) [0|1] ""  MBMU,PC
 SG_ ST_Insulation_42 : 19|2@1+ (1,0) [0|3] ""  MBMU,PC
 SG_ ST_PowerDown_42 : 21|3@1+ (1,0) [0|7] ""  MBMU,PC
 SG_ ST_pwr12V_42 : 24|1@1+ (1,0) [0|1] ""  MBMU,PC
 SG_ ST_pwr5V_42 : 25|1@1+ (1,0) [0|1] ""  MBMU,PC
 SG_ ST_pwr24V_42 : 26|1@1+ (1,0) [0|1] ""  MBMU,PC
 SG_ ST_pwrStatus_42 : 27|3@1+ (1,0) [0|7] ""  MBMU,PC
 SG_ S2A_S2_FullChgFlgFromSBMU_42 : 30|8@1+ (1,0) [0|255] ""  MBMU,PC
 SG_ ST_cscStandby_42 : 46|2@1+ (1,0) [0|3] ""  MBMU,PC
 SG_ ST_OffReasonMsg_42 : 48|16@1+ (1,0) [0|65535] ""  MBMU,PC

BO_ 2332229483 S2A_SUMDATA2__43: 8 SBMU
 SG_ CRC_S2A_S2_43 : 0|8@1+ (1,0) [0|255] ""  MBMU,PC
 SG_ ALIV_ST_SW_HVS_43 : 8|4@1+ (1,0) [0|15] ""  MBMU,PC
 SG_ ST_PreCharge_SW_HVS_43 : 12|1@1+ (1,0) [0|1] ""  MBMU,PC
 SG_ ST_Main_POS_SW_HVS_43 : 13|1@1+ (1,0) [0|1] ""  MBMU,PC
 SG_ ST_Main_NEG_SW_HVS_43 : 14|1@1+ (1,0) [0|1] ""  MBMU,PC
 SG_ ST_System_43 : 17|1@1+ (1,0) [0|1] ""  MBMU,PC
 SG_ ST_CALIBRATION_43 : 18|1@1+ (1,0) [0|1] ""  MBMU,PC
 SG_ ST_Insulation_43 : 19|2@1+ (1,0) [0|3] ""  MBMU,PC
 SG_ ST_PowerDown_43 : 21|3@1+ (1,0) [0|7] ""  MBMU,PC
 SG_ ST_pwr12V_43 : 24|1@1+ (1,0) [0|1] ""  MBMU,PC
 SG_ ST_pwr5V_43 : 25|1@1+ (1,0) [0|1] ""  MBMU,PC
 SG_ ST_pwr24V_43 : 26|1@1+ (1,0) [0|1] ""  MBMU,PC
 SG_ ST_pwrStatus_43 : 27|3@1+ (1,0) [0|7] ""  MBMU,PC
 SG_ S2A_S2_FullChgFlgFromSBMU_43 : 30|8@1+ (1,0) [0|255] ""  MBMU,PC
 SG_ ST_cscStandby_43 : 46|2@1+ (1,0) [0|3] ""  MBMU,PC
 SG_ ST_OffReasonMsg_43 : 48|16@1+ (1,0) [0|65535] ""  MBMU,PC

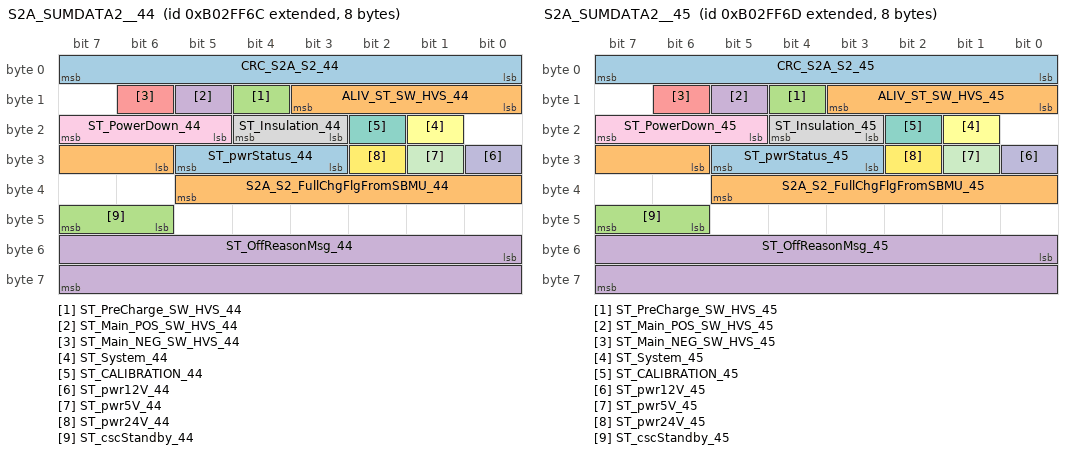
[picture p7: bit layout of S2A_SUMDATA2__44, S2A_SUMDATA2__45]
BO_ 2332229484 S2A_SUMDATA2__44: 8 SBMU
 SG_ CRC_S2A_S2_44 : 0|8@1+ (1,0) [0|255] ""  MBMU,PC
 SG_ ALIV_ST_SW_HVS_44 : 8|4@1+ (1,0) [0|15] ""  MBMU,PC
 SG_ ST_PreCharge_SW_HVS_44 : 12|1@1+ (1,0) [0|1] ""  MBMU,PC
 SG_ ST_Main_POS_SW_HVS_44 : 13|1@1+ (1,0) [0|1] ""  MBMU,PC
 SG_ ST_Main_NEG_SW_HVS_44 : 14|1@1+ (1,0) [0|1] ""  MBMU,PC
 SG_ ST_System_44 : 17|1@1+ (1,0) [0|1] ""  MBMU,PC
 SG_ ST_CALIBRATION_44 : 18|1@1+ (1,0) [0|1] ""  MBMU,PC
 SG_ ST_Insulation_44 : 19|2@1+ (1,0) [0|3] ""  MBMU,PC
 SG_ ST_PowerDown_44 : 21|3@1+ (1,0) [0|7] ""  MBMU,PC
 SG_ ST_pwr12V_44 : 24|1@1+ (1,0) [0|1] ""  MBMU,PC
 SG_ ST_pwr5V_44 : 25|1@1+ (1,0) [0|1] ""  MBMU,PC
 SG_ ST_pwr24V_44 : 26|1@1+ (1,0) [0|1] ""  MBMU,PC
 SG_ ST_pwrStatus_44 : 27|3@1+ (1,0) [0|7] ""  MBMU,PC
 SG_ S2A_S2_FullChgFlgFromSBMU_44 : 30|8@1+ (1,0) [0|255] ""  MBMU,PC
 SG_ ST_cscStandby_44 : 46|2@1+ (1,0) [0|3] ""  MBMU,PC
 SG_ ST_OffReasonMsg_44 : 48|16@1+ (1,0) [0|65535] ""  MBMU,PC

BO_ 2332229485 S2A_SUMDATA2__45: 8 SBMU
 SG_ CRC_S2A_S2_45 : 0|8@1+ (1,0) [0|255] ""  MBMU,PC
 SG_ ALIV_ST_SW_HVS_45 : 8|4@1+ (1,0) [0|15] ""  MBMU,PC
 SG_ ST_PreCharge_SW_HVS_45 : 12|1@1+ (1,0) [0|1] ""  MBMU,PC
 SG_ ST_Main_POS_SW_HVS_45 : 13|1@1+ (1,0) [0|1] ""  MBMU,PC
 SG_ ST_Main_NEG_SW_HVS_45 : 14|1@1+ (1,0) [0|1] ""  MBMU,PC
 SG_ ST_System_45 : 17|1@1+ (1,0) [0|1] ""  MBMU,PC
 SG_ ST_CALIBRATION_45 : 18|1@1+ (1,0) [0|1] ""  MBMU,PC
 SG_ ST_Insulation_45 : 19|2@1+ (1,0) [0|3] ""  MBMU,PC
 SG_ ST_PowerDown_45 : 21|3@1+ (1,0) [0|7] ""  MBMU,PC
 SG_ ST_pwr12V_45 : 24|1@1+ (1,0) [0|1] ""  MBMU,PC
 SG_ ST_pwr5V_45 : 25|1@1+ (1,0) [0|1] ""  MBMU,PC
 SG_ ST_pwr24V_45 : 26|1@1+ (1,0) [0|1] ""  MBMU,PC
 SG_ ST_pwrStatus_45 : 27|3@1+ (1,0) [0|7] ""  MBMU,PC
 SG_ S2A_S2_FullChgFlgFromSBMU_45 : 30|8@1+ (1,0) [0|255] ""  MBMU,PC
 SG_ ST_cscStandby_45 : 46|2@1+ (1,0) [0|3] ""  MBMU,PC
 SG_ ST_OffReasonMsg_45 : 48|16@1+ (1,0) [0|65535] ""  MBMU,PC

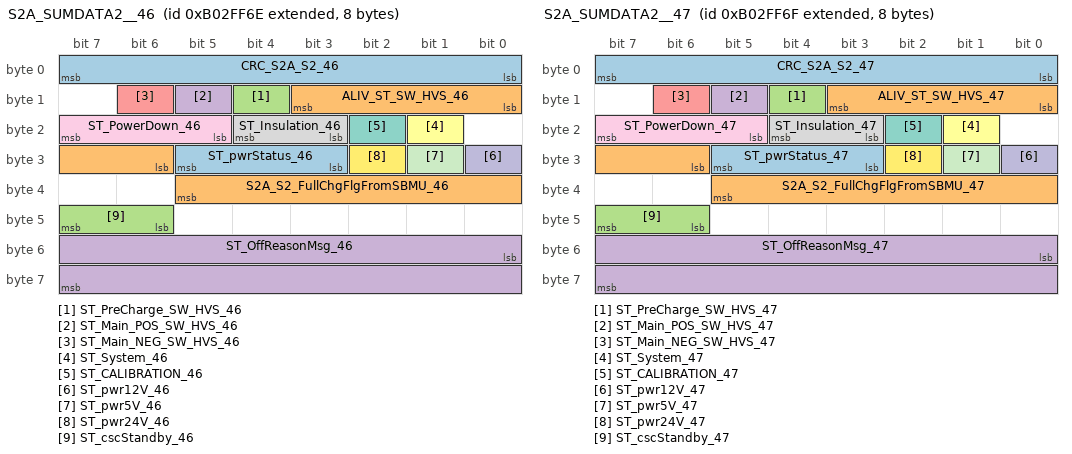
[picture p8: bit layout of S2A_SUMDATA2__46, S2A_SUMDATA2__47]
BO_ 2332229486 S2A_SUMDATA2__46: 8 SBMU
 SG_ CRC_S2A_S2_46 : 0|8@1+ (1,0) [0|255] ""  MBMU,PC
 SG_ ALIV_ST_SW_HVS_46 : 8|4@1+ (1,0) [0|15] ""  MBMU,PC
 SG_ ST_PreCharge_SW_HVS_46 : 12|1@1+ (1,0) [0|1] ""  MBMU,PC
 SG_ ST_Main_POS_SW_HVS_46 : 13|1@1+ (1,0) [0|1] ""  MBMU,PC
 SG_ ST_Main_NEG_SW_HVS_46 : 14|1@1+ (1,0) [0|1] ""  MBMU,PC
 SG_ ST_System_46 : 17|1@1+ (1,0) [0|1] ""  MBMU,PC
 SG_ ST_CALIBRATION_46 : 18|1@1+ (1,0) [0|1] ""  MBMU,PC
 SG_ ST_Insulation_46 : 19|2@1+ (1,0) [0|3] ""  MBMU,PC
 SG_ ST_PowerDown_46 : 21|3@1+ (1,0) [0|7] ""  MBMU,PC
 SG_ ST_pwr12V_46 : 24|1@1+ (1,0) [0|1] ""  MBMU,PC
 SG_ ST_pwr5V_46 : 25|1@1+ (1,0) [0|1] ""  MBMU,PC
 SG_ ST_pwr24V_46 : 26|1@1+ (1,0) [0|1] ""  MBMU,PC
 SG_ ST_pwrStatus_46 : 27|3@1+ (1,0) [0|7] ""  MBMU,PC
 SG_ S2A_S2_FullChgFlgFromSBMU_46 : 30|8@1+ (1,0) [0|255] ""  MBMU,PC
 SG_ ST_cscStandby_46 : 46|2@1+ (1,0) [0|3] ""  MBMU,PC
 SG_ ST_OffReasonMsg_46 : 48|16@1+ (1,0) [0|65535] ""  MBMU,PC

BO_ 2332229487 S2A_SUMDATA2__47: 8 SBMU
 SG_ CRC_S2A_S2_47 : 0|8@1+ (1,0) [0|255] ""  MBMU,PC
 SG_ ALIV_ST_SW_HVS_47 : 8|4@1+ (1,0) [0|15] ""  MBMU,PC
 SG_ ST_PreCharge_SW_HVS_47 : 12|1@1+ (1,0) [0|1] ""  MBMU,PC
 SG_ ST_Main_POS_SW_HVS_47 : 13|1@1+ (1,0) [0|1] ""  MBMU,PC
 SG_ ST_Main_NEG_SW_HVS_47 : 14|1@1+ (1,0) [0|1] ""  MBMU,PC
 SG_ ST_System_47 : 17|1@1+ (1,0) [0|1] ""  MBMU,PC
 SG_ ST_CALIBRATION_47 : 18|1@1+ (1,0) [0|1] ""  MBMU,PC
 SG_ ST_Insulation_47 : 19|2@1+ (1,0) [0|3] ""  MBMU,PC
 SG_ ST_PowerDown_47 : 21|3@1+ (1,0) [0|7] ""  MBMU,PC
 SG_ ST_pwr12V_47 : 24|1@1+ (1,0) [0|1] ""  MBMU,PC
 SG_ ST_pwr5V_47 : 25|1@1+ (1,0) [0|1] ""  MBMU,PC
 SG_ ST_pwr24V_47 : 26|1@1+ (1,0) [0|1] ""  MBMU,PC
 SG_ ST_pwrStatus_47 : 27|3@1+ (1,0) [0|7] ""  MBMU,PC
 SG_ S2A_S2_FullChgFlgFromSBMU_47 : 30|8@1+ (1,0) [0|255] ""  MBMU,PC
 SG_ ST_cscStandby_47 : 46|2@1+ (1,0) [0|3] ""  MBMU,PC
 SG_ ST_OffReasonMsg_47 : 48|16@1+ (1,0) [0|65535] ""  MBMU,PC

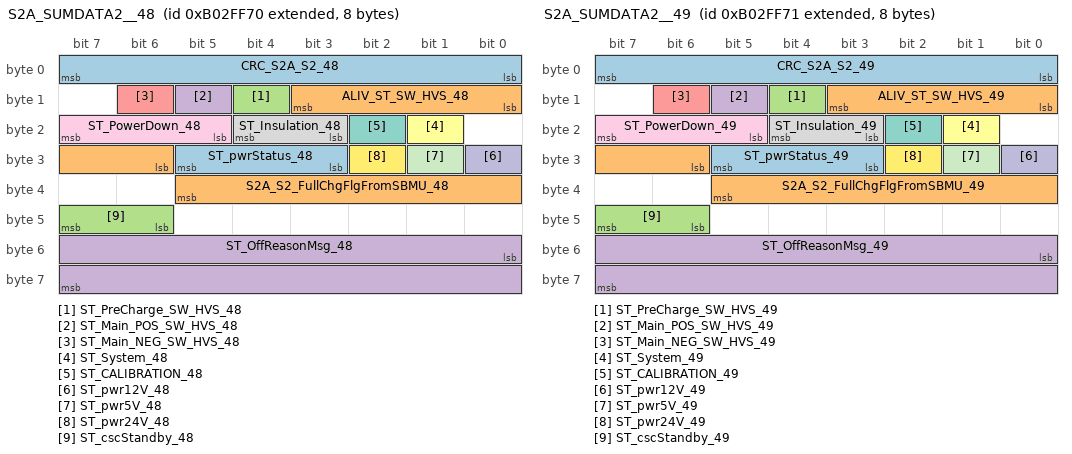
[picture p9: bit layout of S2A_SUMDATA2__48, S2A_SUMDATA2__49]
BO_ 2332229488 S2A_SUMDATA2__48: 8 SBMU
 SG_ CRC_S2A_S2_48 : 0|8@1+ (1,0) [0|255] ""  MBMU,PC
 SG_ ALIV_ST_SW_HVS_48 : 8|4@1+ (1,0) [0|15] ""  MBMU,PC
 SG_ ST_PreCharge_SW_HVS_48 : 12|1@1+ (1,0) [0|1] ""  MBMU,PC
 SG_ ST_Main_POS_SW_HVS_48 : 13|1@1+ (1,0) [0|1] ""  MBMU,PC
 SG_ ST_Main_NEG_SW_HVS_48 : 14|1@1+ (1,0) [0|1] ""  MBMU,PC
 SG_ ST_System_48 : 17|1@1+ (1,0) [0|1] ""  MBMU,PC
 SG_ ST_CALIBRATION_48 : 18|1@1+ (1,0) [0|1] ""  MBMU,PC
 SG_ ST_Insulation_48 : 19|2@1+ (1,0) [0|3] ""  MBMU,PC
 SG_ ST_PowerDown_48 : 21|3@1+ (1,0) [0|7] ""  MBMU,PC
 SG_ ST_pwr12V_48 : 24|1@1+ (1,0) [0|1] ""  MBMU,PC
 SG_ ST_pwr5V_48 : 25|1@1+ (1,0) [0|1] ""  MBMU,PC
 SG_ ST_pwr24V_48 : 26|1@1+ (1,0) [0|1] ""  MBMU,PC
 SG_ ST_pwrStatus_48 : 27|3@1+ (1,0) [0|7] ""  MBMU,PC
 SG_ S2A_S2_FullChgFlgFromSBMU_48 : 30|8@1+ (1,0) [0|255] ""  MBMU,PC
 SG_ ST_cscStandby_48 : 46|2@1+ (1,0) [0|3] ""  MBMU,PC
 SG_ ST_OffReasonMsg_48 : 48|16@1+ (1,0) [0|65535] ""  MBMU,PC

BO_ 2332229489 S2A_SUMDATA2__49: 8 SBMU
 SG_ CRC_S2A_S2_49 : 0|8@1+ (1,0) [0|255] ""  MBMU,PC
 SG_ ALIV_ST_SW_HVS_49 : 8|4@1+ (1,0) [0|15] ""  MBMU,PC
 SG_ ST_PreCharge_SW_HVS_49 : 12|1@1+ (1,0) [0|1] ""  MBMU,PC
 SG_ ST_Main_POS_SW_HVS_49 : 13|1@1+ (1,0) [0|1] ""  MBMU,PC
 SG_ ST_Main_NEG_SW_HVS_49 : 14|1@1+ (1,0) [0|1] ""  MBMU,PC
 SG_ ST_System_49 : 17|1@1+ (1,0) [0|1] ""  MBMU,PC
 SG_ ST_CALIBRATION_49 : 18|1@1+ (1,0) [0|1] ""  MBMU,PC
 SG_ ST_Insulation_49 : 19|2@1+ (1,0) [0|3] ""  MBMU,PC
 SG_ ST_PowerDown_49 : 21|3@1+ (1,0) [0|7] ""  MBMU,PC
 SG_ ST_pwr12V_49 : 24|1@1+ (1,0) [0|1] ""  MBMU,PC
 SG_ ST_pwr5V_49 : 25|1@1+ (1,0) [0|1] ""  MBMU,PC
 SG_ ST_pwr24V_49 : 26|1@1+ (1,0) [0|1] ""  MBMU,PC
 SG_ ST_pwrStatus_49 : 27|3@1+ (1,0) [0|7] ""  MBMU,PC
 SG_ S2A_S2_FullChgFlgFromSBMU_49 : 30|8@1+ (1,0) [0|255] ""  MBMU,PC
 SG_ ST_cscStandby_49 : 46|2@1+ (1,0) [0|3] ""  MBMU,PC
 SG_ ST_OffReasonMsg_49 : 48|16@1+ (1,0) [0|65535] ""  MBMU,PC

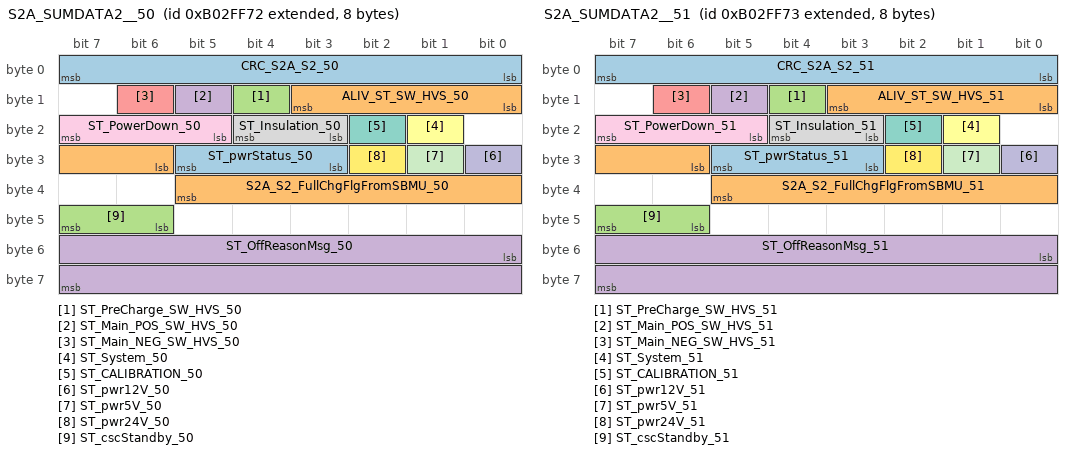
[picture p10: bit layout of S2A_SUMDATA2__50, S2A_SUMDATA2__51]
BO_ 2332229490 S2A_SUMDATA2__50: 8 SBMU
 SG_ CRC_S2A_S2_50 : 0|8@1+ (1,0) [0|255] ""  MBMU,PC
 SG_ ALIV_ST_SW_HVS_50 : 8|4@1+ (1,0) [0|15] ""  MBMU,PC
 SG_ ST_PreCharge_SW_HVS_50 : 12|1@1+ (1,0) [0|1] ""  MBMU,PC
 SG_ ST_Main_POS_SW_HVS_50 : 13|1@1+ (1,0) [0|1] ""  MBMU,PC
 SG_ ST_Main_NEG_SW_HVS_50 : 14|1@1+ (1,0) [0|1] ""  MBMU,PC
 SG_ ST_System_50 : 17|1@1+ (1,0) [0|1] ""  MBMU,PC
 SG_ ST_CALIBRATION_50 : 18|1@1+ (1,0) [0|1] ""  MBMU,PC
 SG_ ST_Insulation_50 : 19|2@1+ (1,0) [0|3] ""  MBMU,PC
 SG_ ST_PowerDown_50 : 21|3@1+ (1,0) [0|7] ""  MBMU,PC
 SG_ ST_pwr12V_50 : 24|1@1+ (1,0) [0|1] ""  MBMU,PC
 SG_ ST_pwr5V_50 : 25|1@1+ (1,0) [0|1] ""  MBMU,PC
 SG_ ST_pwr24V_50 : 26|1@1+ (1,0) [0|1] ""  MBMU,PC
 SG_ ST_pwrStatus_50 : 27|3@1+ (1,0) [0|7] ""  MBMU,PC
 SG_ S2A_S2_FullChgFlgFromSBMU_50 : 30|8@1+ (1,0) [0|255] ""  MBMU,PC
 SG_ ST_cscStandby_50 : 46|2@1+ (1,0) [0|3] ""  MBMU,PC
 SG_ ST_OffReasonMsg_50 : 48|16@1+ (1,0) [0|65535] ""  MBMU,PC

BO_ 2332229491 S2A_SUMDATA2__51: 8 SBMU
 SG_ CRC_S2A_S2_51 : 0|8@1+ (1,0) [0|255] ""  MBMU,PC
 SG_ ALIV_ST_SW_HVS_51 : 8|4@1+ (1,0) [0|15] ""  MBMU,PC
 SG_ ST_PreCharge_SW_HVS_51 : 12|1@1+ (1,0) [0|1] ""  MBMU,PC
 SG_ ST_Main_POS_SW_HVS_51 : 13|1@1+ (1,0) [0|1] ""  MBMU,PC
 SG_ ST_Main_NEG_SW_HVS_51 : 14|1@1+ (1,0) [0|1] ""  MBMU,PC
 SG_ ST_System_51 : 17|1@1+ (1,0) [0|1] ""  MBMU,PC
 SG_ ST_CALIBRATION_51 : 18|1@1+ (1,0) [0|1] ""  MBMU,PC
 SG_ ST_Insulation_51 : 19|2@1+ (1,0) [0|3] ""  MBMU,PC
 SG_ ST_PowerDown_51 : 21|3@1+ (1,0) [0|7] ""  MBMU,PC
 SG_ ST_pwr12V_51 : 24|1@1+ (1,0) [0|1] ""  MBMU,PC
 SG_ ST_pwr5V_51 : 25|1@1+ (1,0) [0|1] ""  MBMU,PC
 SG_ ST_pwr24V_51 : 26|1@1+ (1,0) [0|1] ""  MBMU,PC
 SG_ ST_pwrStatus_51 : 27|3@1+ (1,0) [0|7] ""  MBMU,PC
 SG_ S2A_S2_FullChgFlgFromSBMU_51 : 30|8@1+ (1,0) [0|255] ""  MBMU,PC
 SG_ ST_cscStandby_51 : 46|2@1+ (1,0) [0|3] ""  MBMU,PC
 SG_ ST_OffReasonMsg_51 : 48|16@1+ (1,0) [0|65535] ""  MBMU,PC

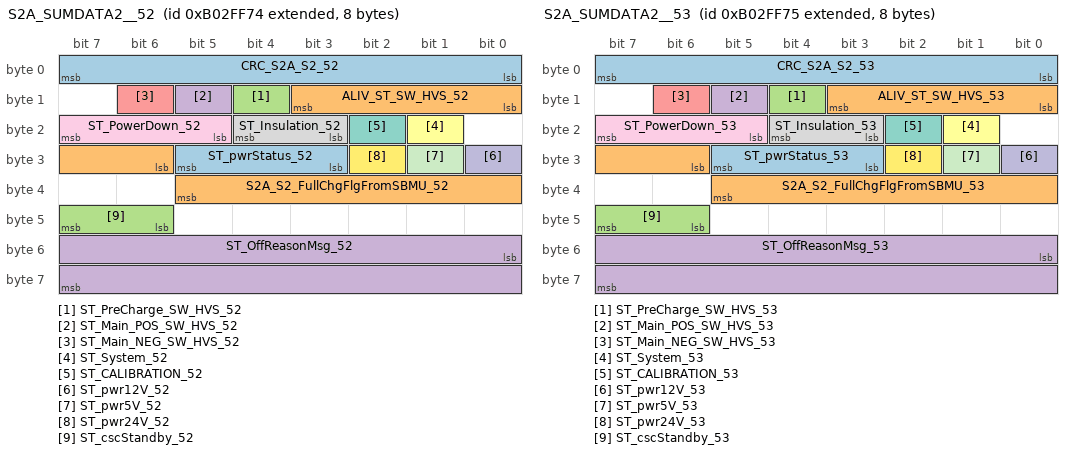
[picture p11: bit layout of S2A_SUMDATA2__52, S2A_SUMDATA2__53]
BO_ 2332229492 S2A_SUMDATA2__52: 8 SBMU
 SG_ CRC_S2A_S2_52 : 0|8@1+ (1,0) [0|255] ""  MBMU,PC
 SG_ ALIV_ST_SW_HVS_52 : 8|4@1+ (1,0) [0|15] ""  MBMU,PC
 SG_ ST_PreCharge_SW_HVS_52 : 12|1@1+ (1,0) [0|1] ""  MBMU,PC
 SG_ ST_Main_POS_SW_HVS_52 : 13|1@1+ (1,0) [0|1] ""  MBMU,PC
 SG_ ST_Main_NEG_SW_HVS_52 : 14|1@1+ (1,0) [0|1] ""  MBMU,PC
 SG_ ST_System_52 : 17|1@1+ (1,0) [0|1] ""  MBMU,PC
 SG_ ST_CALIBRATION_52 : 18|1@1+ (1,0) [0|1] ""  MBMU,PC
 SG_ ST_Insulation_52 : 19|2@1+ (1,0) [0|3] ""  MBMU,PC
 SG_ ST_PowerDown_52 : 21|3@1+ (1,0) [0|7] ""  MBMU,PC
 SG_ ST_pwr12V_52 : 24|1@1+ (1,0) [0|1] ""  MBMU,PC
 SG_ ST_pwr5V_52 : 25|1@1+ (1,0) [0|1] ""  MBMU,PC
 SG_ ST_pwr24V_52 : 26|1@1+ (1,0) [0|1] ""  MBMU,PC
 SG_ ST_pwrStatus_52 : 27|3@1+ (1,0) [0|7] ""  MBMU,PC
 SG_ S2A_S2_FullChgFlgFromSBMU_52 : 30|8@1+ (1,0) [0|255] ""  MBMU,PC
 SG_ ST_cscStandby_52 : 46|2@1+ (1,0) [0|3] ""  MBMU,PC
 SG_ ST_OffReasonMsg_52 : 48|16@1+ (1,0) [0|65535] ""  MBMU,PC

BO_ 2332229493 S2A_SUMDATA2__53: 8 SBMU
 SG_ CRC_S2A_S2_53 : 0|8@1+ (1,0) [0|255] ""  MBMU,PC
 SG_ ALIV_ST_SW_HVS_53 : 8|4@1+ (1,0) [0|15] ""  MBMU,PC
 SG_ ST_PreCharge_SW_HVS_53 : 12|1@1+ (1,0) [0|1] ""  MBMU,PC
 SG_ ST_Main_POS_SW_HVS_53 : 13|1@1+ (1,0) [0|1] ""  MBMU,PC
 SG_ ST_Main_NEG_SW_HVS_53 : 14|1@1+ (1,0) [0|1] ""  MBMU,PC
 SG_ ST_System_53 : 17|1@1+ (1,0) [0|1] ""  MBMU,PC
 SG_ ST_CALIBRATION_53 : 18|1@1+ (1,0) [0|1] ""  MBMU,PC
 SG_ ST_Insulation_53 : 19|2@1+ (1,0) [0|3] ""  MBMU,PC
 SG_ ST_PowerDown_53 : 21|3@1+ (1,0) [0|7] ""  MBMU,PC
 SG_ ST_pwr12V_53 : 24|1@1+ (1,0) [0|1] ""  MBMU,PC
 SG_ ST_pwr5V_53 : 25|1@1+ (1,0) [0|1] ""  MBMU,PC
 SG_ ST_pwr24V_53 : 26|1@1+ (1,0) [0|1] ""  MBMU,PC
 SG_ ST_pwrStatus_53 : 27|3@1+ (1,0) [0|7] ""  MBMU,PC
 SG_ S2A_S2_FullChgFlgFromSBMU_53 : 30|8@1+ (1,0) [0|255] ""  MBMU,PC
 SG_ ST_cscStandby_53 : 46|2@1+ (1,0) [0|3] ""  MBMU,PC
 SG_ ST_OffReasonMsg_53 : 48|16@1+ (1,0) [0|65535] ""  MBMU,PC

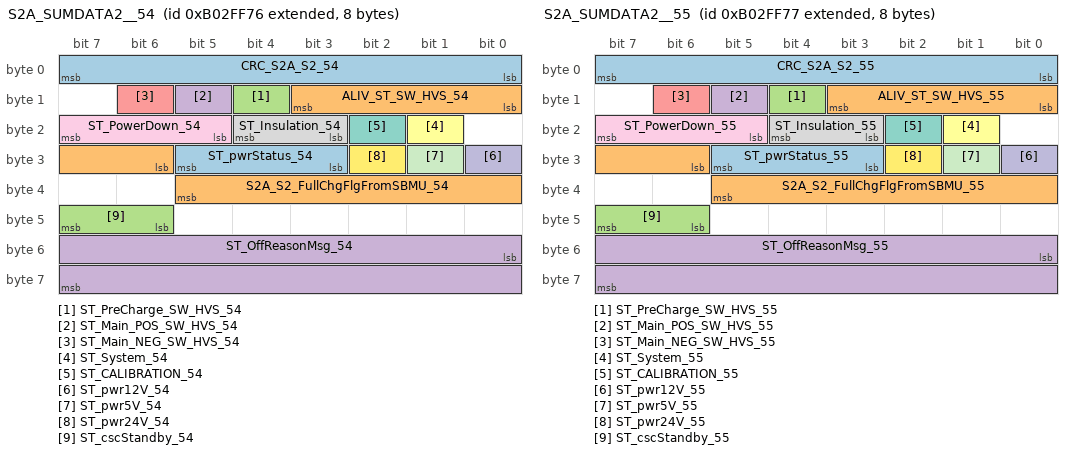
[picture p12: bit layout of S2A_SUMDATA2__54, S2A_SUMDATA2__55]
BO_ 2332229494 S2A_SUMDATA2__54: 8 SBMU
 SG_ CRC_S2A_S2_54 : 0|8@1+ (1,0) [0|255] ""  MBMU,PC
 SG_ ALIV_ST_SW_HVS_54 : 8|4@1+ (1,0) [0|15] ""  MBMU,PC
 SG_ ST_PreCharge_SW_HVS_54 : 12|1@1+ (1,0) [0|1] ""  MBMU,PC
 SG_ ST_Main_POS_SW_HVS_54 : 13|1@1+ (1,0) [0|1] ""  MBMU,PC
 SG_ ST_Main_NEG_SW_HVS_54 : 14|1@1+ (1,0) [0|1] ""  MBMU,PC
 SG_ ST_System_54 : 17|1@1+ (1,0) [0|1] ""  MBMU,PC
 SG_ ST_CALIBRATION_54 : 18|1@1+ (1,0) [0|1] ""  MBMU,PC
 SG_ ST_Insulation_54 : 19|2@1+ (1,0) [0|3] ""  MBMU,PC
 SG_ ST_PowerDown_54 : 21|3@1+ (1,0) [0|7] ""  MBMU,PC
 SG_ ST_pwr12V_54 : 24|1@1+ (1,0) [0|1] ""  MBMU,PC
 SG_ ST_pwr5V_54 : 25|1@1+ (1,0) [0|1] ""  MBMU,PC
 SG_ ST_pwr24V_54 : 26|1@1+ (1,0) [0|1] ""  MBMU,PC
 SG_ ST_pwrStatus_54 : 27|3@1+ (1,0) [0|7] ""  MBMU,PC
 SG_ S2A_S2_FullChgFlgFromSBMU_54 : 30|8@1+ (1,0) [0|255] ""  MBMU,PC
 SG_ ST_cscStandby_54 : 46|2@1+ (1,0) [0|3] ""  MBMU,PC
 SG_ ST_OffReasonMsg_54 : 48|16@1+ (1,0) [0|65535] ""  MBMU,PC

BO_ 2332229495 S2A_SUMDATA2__55: 8 SBMU
 SG_ CRC_S2A_S2_55 : 0|8@1+ (1,0) [0|255] ""  MBMU,PC
 SG_ ALIV_ST_SW_HVS_55 : 8|4@1+ (1,0) [0|15] ""  MBMU,PC
 SG_ ST_PreCharge_SW_HVS_55 : 12|1@1+ (1,0) [0|1] ""  MBMU,PC
 SG_ ST_Main_POS_SW_HVS_55 : 13|1@1+ (1,0) [0|1] ""  MBMU,PC
 SG_ ST_Main_NEG_SW_HVS_55 : 14|1@1+ (1,0) [0|1] ""  MBMU,PC
 SG_ ST_System_55 : 17|1@1+ (1,0) [0|1] ""  MBMU,PC
 SG_ ST_CALIBRATION_55 : 18|1@1+ (1,0) [0|1] ""  MBMU,PC
 SG_ ST_Insulation_55 : 19|2@1+ (1,0) [0|3] ""  MBMU,PC
 SG_ ST_PowerDown_55 : 21|3@1+ (1,0) [0|7] ""  MBMU,PC
 SG_ ST_pwr12V_55 : 24|1@1+ (1,0) [0|1] ""  MBMU,PC
 SG_ ST_pwr5V_55 : 25|1@1+ (1,0) [0|1] ""  MBMU,PC
 SG_ ST_pwr24V_55 : 26|1@1+ (1,0) [0|1] ""  MBMU,PC
 SG_ ST_pwrStatus_55 : 27|3@1+ (1,0) [0|7] ""  MBMU,PC
 SG_ S2A_S2_FullChgFlgFromSBMU_55 : 30|8@1+ (1,0) [0|255] ""  MBMU,PC
 SG_ ST_cscStandby_55 : 46|2@1+ (1,0) [0|3] ""  MBMU,PC
 SG_ ST_OffReasonMsg_55 : 48|16@1+ (1,0) [0|65535] ""  MBMU,PC

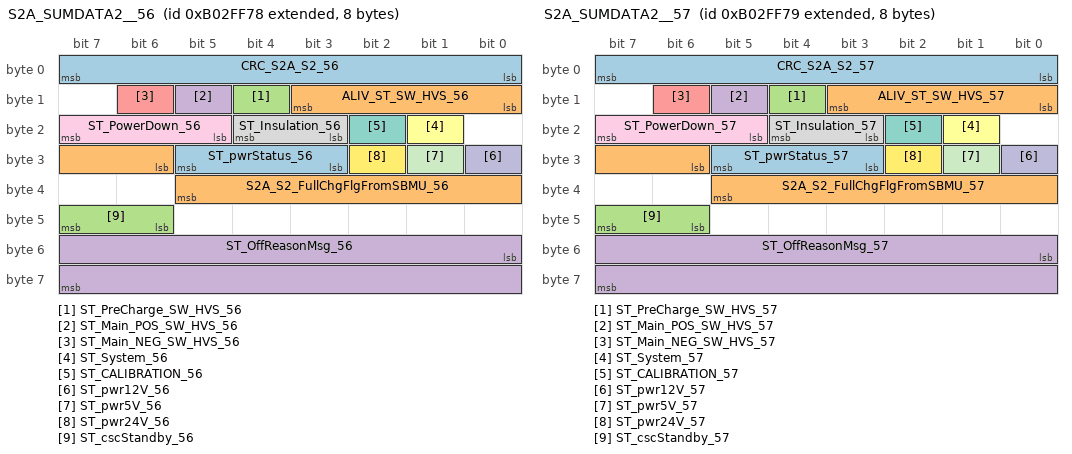
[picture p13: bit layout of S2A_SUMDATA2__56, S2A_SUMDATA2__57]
BO_ 2332229496 S2A_SUMDATA2__56: 8 SBMU
 SG_ CRC_S2A_S2_56 : 0|8@1+ (1,0) [0|255] ""  MBMU,PC
 SG_ ALIV_ST_SW_HVS_56 : 8|4@1+ (1,0) [0|15] ""  MBMU,PC
 SG_ ST_PreCharge_SW_HVS_56 : 12|1@1+ (1,0) [0|1] ""  MBMU,PC
 SG_ ST_Main_POS_SW_HVS_56 : 13|1@1+ (1,0) [0|1] ""  MBMU,PC
 SG_ ST_Main_NEG_SW_HVS_56 : 14|1@1+ (1,0) [0|1] ""  MBMU,PC
 SG_ ST_System_56 : 17|1@1+ (1,0) [0|1] ""  MBMU,PC
 SG_ ST_CALIBRATION_56 : 18|1@1+ (1,0) [0|1] ""  MBMU,PC
 SG_ ST_Insulation_56 : 19|2@1+ (1,0) [0|3] ""  MBMU,PC
 SG_ ST_PowerDown_56 : 21|3@1+ (1,0) [0|7] ""  MBMU,PC
 SG_ ST_pwr12V_56 : 24|1@1+ (1,0) [0|1] ""  MBMU,PC
 SG_ ST_pwr5V_56 : 25|1@1+ (1,0) [0|1] ""  MBMU,PC
 SG_ ST_pwr24V_56 : 26|1@1+ (1,0) [0|1] ""  MBMU,PC
 SG_ ST_pwrStatus_56 : 27|3@1+ (1,0) [0|7] ""  MBMU,PC
 SG_ S2A_S2_FullChgFlgFromSBMU_56 : 30|8@1+ (1,0) [0|255] ""  MBMU,PC
 SG_ ST_cscStandby_56 : 46|2@1+ (1,0) [0|3] ""  MBMU,PC
 SG_ ST_OffReasonMsg_56 : 48|16@1+ (1,0) [0|65535] ""  MBMU,PC

BO_ 2332229497 S2A_SUMDATA2__57: 8 SBMU
 SG_ CRC_S2A_S2_57 : 0|8@1+ (1,0) [0|255] ""  MBMU,PC
 SG_ ALIV_ST_SW_HVS_57 : 8|4@1+ (1,0) [0|15] ""  MBMU,PC
 SG_ ST_PreCharge_SW_HVS_57 : 12|1@1+ (1,0) [0|1] ""  MBMU,PC
 SG_ ST_Main_POS_SW_HVS_57 : 13|1@1+ (1,0) [0|1] ""  MBMU,PC
 SG_ ST_Main_NEG_SW_HVS_57 : 14|1@1+ (1,0) [0|1] ""  MBMU,PC
 SG_ ST_System_57 : 17|1@1+ (1,0) [0|1] ""  MBMU,PC
 SG_ ST_CALIBRATION_57 : 18|1@1+ (1,0) [0|1] ""  MBMU,PC
 SG_ ST_Insulation_57 : 19|2@1+ (1,0) [0|3] ""  MBMU,PC
 SG_ ST_PowerDown_57 : 21|3@1+ (1,0) [0|7] ""  MBMU,PC
 SG_ ST_pwr12V_57 : 24|1@1+ (1,0) [0|1] ""  MBMU,PC
 SG_ ST_pwr5V_57 : 25|1@1+ (1,0) [0|1] ""  MBMU,PC
 SG_ ST_pwr24V_57 : 26|1@1+ (1,0) [0|1] ""  MBMU,PC
 SG_ ST_pwrStatus_57 : 27|3@1+ (1,0) [0|7] ""  MBMU,PC
 SG_ S2A_S2_FullChgFlgFromSBMU_57 : 30|8@1+ (1,0) [0|255] ""  MBMU,PC
 SG_ ST_cscStandby_57 : 46|2@1+ (1,0) [0|3] ""  MBMU,PC
 SG_ ST_OffReasonMsg_57 : 48|16@1+ (1,0) [0|65535] ""  MBMU,PC

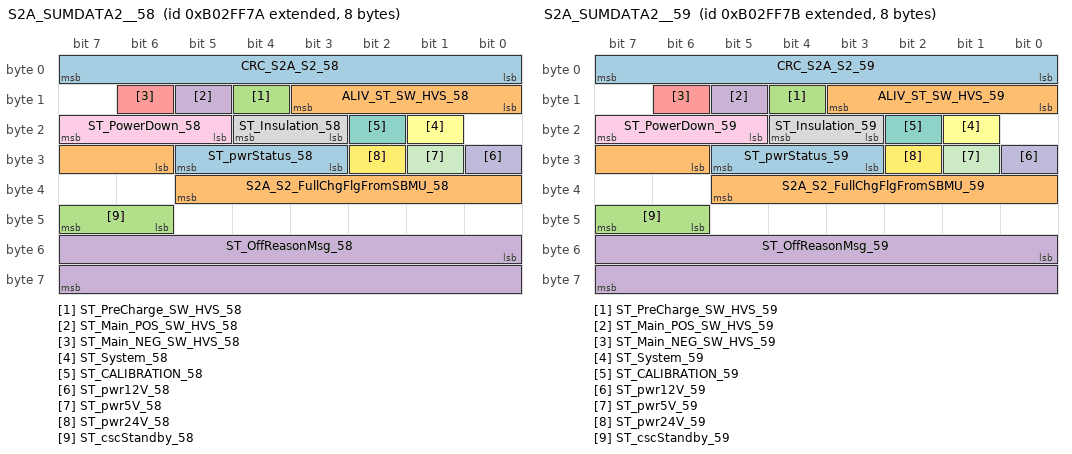
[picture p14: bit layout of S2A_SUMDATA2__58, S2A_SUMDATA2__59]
BO_ 2332229498 S2A_SUMDATA2__58: 8 SBMU
 SG_ CRC_S2A_S2_58 : 0|8@1+ (1,0) [0|255] ""  MBMU,PC
 SG_ ALIV_ST_SW_HVS_58 : 8|4@1+ (1,0) [0|15] ""  MBMU,PC
 SG_ ST_PreCharge_SW_HVS_58 : 12|1@1+ (1,0) [0|1] ""  MBMU,PC
 SG_ ST_Main_POS_SW_HVS_58 : 13|1@1+ (1,0) [0|1] ""  MBMU,PC
 SG_ ST_Main_NEG_SW_HVS_58 : 14|1@1+ (1,0) [0|1] ""  MBMU,PC
 SG_ ST_System_58 : 17|1@1+ (1,0) [0|1] ""  MBMU,PC
 SG_ ST_CALIBRATION_58 : 18|1@1+ (1,0) [0|1] ""  MBMU,PC
 SG_ ST_Insulation_58 : 19|2@1+ (1,0) [0|3] ""  MBMU,PC
 SG_ ST_PowerDown_58 : 21|3@1+ (1,0) [0|7] ""  MBMU,PC
 SG_ ST_pwr12V_58 : 24|1@1+ (1,0) [0|1] ""  MBMU,PC
 SG_ ST_pwr5V_58 : 25|1@1+ (1,0) [0|1] ""  MBMU,PC
 SG_ ST_pwr24V_58 : 26|1@1+ (1,0) [0|1] ""  MBMU,PC
 SG_ ST_pwrStatus_58 : 27|3@1+ (1,0) [0|7] ""  MBMU,PC
 SG_ S2A_S2_FullChgFlgFromSBMU_58 : 30|8@1+ (1,0) [0|255] ""  MBMU,PC
 SG_ ST_cscStandby_58 : 46|2@1+ (1,0) [0|3] ""  MBMU,PC
 SG_ ST_OffReasonMsg_58 : 48|16@1+ (1,0) [0|65535] ""  MBMU,PC

BO_ 2332229499 S2A_SUMDATA2__59: 8 SBMU
 SG_ CRC_S2A_S2_59 : 0|8@1+ (1,0) [0|255] ""  MBMU,PC
 SG_ ALIV_ST_SW_HVS_59 : 8|4@1+ (1,0) [0|15] ""  MBMU,PC
 SG_ ST_PreCharge_SW_HVS_59 : 12|1@1+ (1,0) [0|1] ""  MBMU,PC
 SG_ ST_Main_POS_SW_HVS_59 : 13|1@1+ (1,0) [0|1] ""  MBMU,PC
 SG_ ST_Main_NEG_SW_HVS_59 : 14|1@1+ (1,0) [0|1] ""  MBMU,PC
 SG_ ST_System_59 : 17|1@1+ (1,0) [0|1] ""  MBMU,PC
 SG_ ST_CALIBRATION_59 : 18|1@1+ (1,0) [0|1] ""  MBMU,PC
 SG_ ST_Insulation_59 : 19|2@1+ (1,0) [0|3] ""  MBMU,PC
 SG_ ST_PowerDown_59 : 21|3@1+ (1,0) [0|7] ""  MBMU,PC
 SG_ ST_pwr12V_59 : 24|1@1+ (1,0) [0|1] ""  MBMU,PC
 SG_ ST_pwr5V_59 : 25|1@1+ (1,0) [0|1] ""  MBMU,PC
 SG_ ST_pwr24V_59 : 26|1@1+ (1,0) [0|1] ""  MBMU,PC
 SG_ ST_pwrStatus_59 : 27|3@1+ (1,0) [0|7] ""  MBMU,PC
 SG_ S2A_S2_FullChgFlgFromSBMU_59 : 30|8@1+ (1,0) [0|255] ""  MBMU,PC
 SG_ ST_cscStandby_59 : 46|2@1+ (1,0) [0|3] ""  MBMU,PC
 SG_ ST_OffReasonMsg_59 : 48|16@1+ (1,0) [0|65535] ""  MBMU,PC

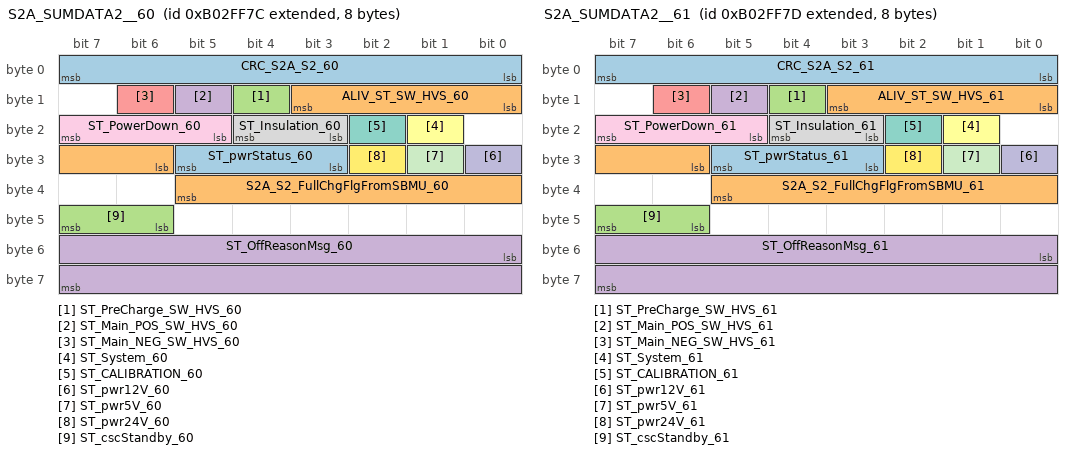
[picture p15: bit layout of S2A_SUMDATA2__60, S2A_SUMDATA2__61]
BO_ 2332229500 S2A_SUMDATA2__60: 8 SBMU
 SG_ CRC_S2A_S2_60 : 0|8@1+ (1,0) [0|255] ""  MBMU,PC
 SG_ ALIV_ST_SW_HVS_60 : 8|4@1+ (1,0) [0|15] ""  MBMU,PC
 SG_ ST_PreCharge_SW_HVS_60 : 12|1@1+ (1,0) [0|1] ""  MBMU,PC
 SG_ ST_Main_POS_SW_HVS_60 : 13|1@1+ (1,0) [0|1] ""  MBMU,PC
 SG_ ST_Main_NEG_SW_HVS_60 : 14|1@1+ (1,0) [0|1] ""  MBMU,PC
 SG_ ST_System_60 : 17|1@1+ (1,0) [0|1] ""  MBMU,PC
 SG_ ST_CALIBRATION_60 : 18|1@1+ (1,0) [0|1] ""  MBMU,PC
 SG_ ST_Insulation_60 : 19|2@1+ (1,0) [0|3] ""  MBMU,PC
 SG_ ST_PowerDown_60 : 21|3@1+ (1,0) [0|7] ""  MBMU,PC
 SG_ ST_pwr12V_60 : 24|1@1+ (1,0) [0|1] ""  MBMU,PC
 SG_ ST_pwr5V_60 : 25|1@1+ (1,0) [0|1] ""  MBMU,PC
 SG_ ST_pwr24V_60 : 26|1@1+ (1,0) [0|1] ""  MBMU,PC
 SG_ ST_pwrStatus_60 : 27|3@1+ (1,0) [0|7] ""  MBMU,PC
 SG_ S2A_S2_FullChgFlgFromSBMU_60 : 30|8@1+ (1,0) [0|255] ""  MBMU,PC
 SG_ ST_cscStandby_60 : 46|2@1+ (1,0) [0|3] ""  MBMU,PC
 SG_ ST_OffReasonMsg_60 : 48|16@1+ (1,0) [0|65535] ""  MBMU,PC

BO_ 2332229501 S2A_SUMDATA2__61: 8 SBMU
 SG_ CRC_S2A_S2_61 : 0|8@1+ (1,0) [0|255] ""  MBMU,PC
 SG_ ALIV_ST_SW_HVS_61 : 8|4@1+ (1,0) [0|15] ""  MBMU,PC
 SG_ ST_PreCharge_SW_HVS_61 : 12|1@1+ (1,0) [0|1] ""  MBMU,PC
 SG_ ST_Main_POS_SW_HVS_61 : 13|1@1+ (1,0) [0|1] ""  MBMU,PC
 SG_ ST_Main_NEG_SW_HVS_61 : 14|1@1+ (1,0) [0|1] ""  MBMU,PC
 SG_ ST_System_61 : 17|1@1+ (1,0) [0|1] ""  MBMU,PC
 SG_ ST_CALIBRATION_61 : 18|1@1+ (1,0) [0|1] ""  MBMU,PC
 SG_ ST_Insulation_61 : 19|2@1+ (1,0) [0|3] ""  MBMU,PC
 SG_ ST_PowerDown_61 : 21|3@1+ (1,0) [0|7] ""  MBMU,PC
 SG_ ST_pwr12V_61 : 24|1@1+ (1,0) [0|1] ""  MBMU,PC
 SG_ ST_pwr5V_61 : 25|1@1+ (1,0) [0|1] ""  MBMU,PC
 SG_ ST_pwr24V_61 : 26|1@1+ (1,0) [0|1] ""  MBMU,PC
 SG_ ST_pwrStatus_61 : 27|3@1+ (1,0) [0|7] ""  MBMU,PC
 SG_ S2A_S2_FullChgFlgFromSBMU_61 : 30|8@1+ (1,0) [0|255] ""  MBMU,PC
 SG_ ST_cscStandby_61 : 46|2@1+ (1,0) [0|3] ""  MBMU,PC
 SG_ ST_OffReasonMsg_61 : 48|16@1+ (1,0) [0|65535] ""  MBMU,PC

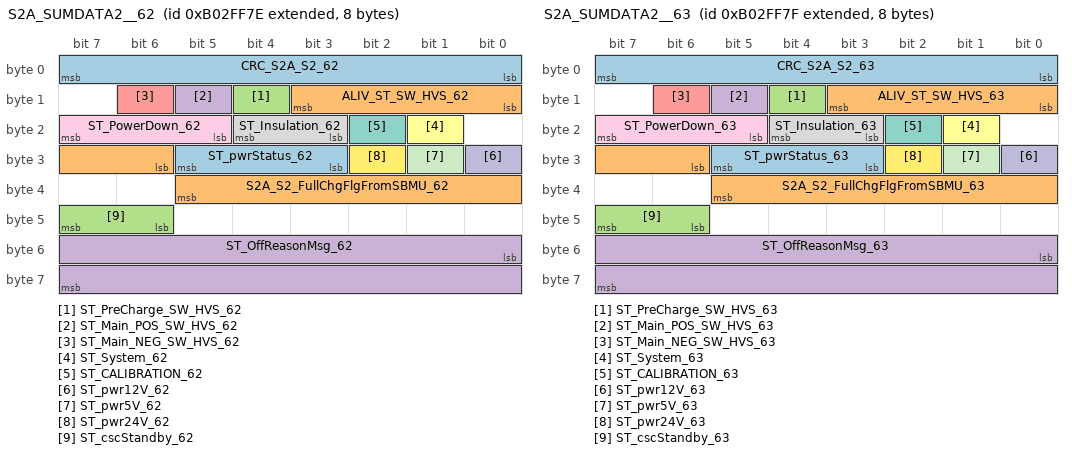
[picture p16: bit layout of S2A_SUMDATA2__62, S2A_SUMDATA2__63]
BO_ 2332229502 S2A_SUMDATA2__62: 8 SBMU
 SG_ CRC_S2A_S2_62 : 0|8@1+ (1,0) [0|255] ""  MBMU,PC
 SG_ ALIV_ST_SW_HVS_62 : 8|4@1+ (1,0) [0|15] ""  MBMU,PC
 SG_ ST_PreCharge_SW_HVS_62 : 12|1@1+ (1,0) [0|1] ""  MBMU,PC
 SG_ ST_Main_POS_SW_HVS_62 : 13|1@1+ (1,0) [0|1] ""  MBMU,PC
 SG_ ST_Main_NEG_SW_HVS_62 : 14|1@1+ (1,0) [0|1] ""  MBMU,PC
 SG_ ST_System_62 : 17|1@1+ (1,0) [0|1] ""  MBMU,PC
 SG_ ST_CALIBRATION_62 : 18|1@1+ (1,0) [0|1] ""  MBMU,PC
 SG_ ST_Insulation_62 : 19|2@1+ (1,0) [0|3] ""  MBMU,PC
 SG_ ST_PowerDown_62 : 21|3@1+ (1,0) [0|7] ""  MBMU,PC
 SG_ ST_pwr12V_62 : 24|1@1+ (1,0) [0|1] ""  MBMU,PC
 SG_ ST_pwr5V_62 : 25|1@1+ (1,0) [0|1] ""  MBMU,PC
 SG_ ST_pwr24V_62 : 26|1@1+ (1,0) [0|1] ""  MBMU,PC
 SG_ ST_pwrStatus_62 : 27|3@1+ (1,0) [0|7] ""  MBMU,PC
 SG_ S2A_S2_FullChgFlgFromSBMU_62 : 30|8@1+ (1,0) [0|255] ""  MBMU,PC
 SG_ ST_cscStandby_62 : 46|2@1+ (1,0) [0|3] ""  MBMU,PC
 SG_ ST_OffReasonMsg_62 : 48|16@1+ (1,0) [0|65535] ""  MBMU,PC

BO_ 2332229503 S2A_SUMDATA2__63: 8 SBMU
 SG_ CRC_S2A_S2_63 : 0|8@1+ (1,0) [0|255] ""  MBMU,PC
 SG_ ALIV_ST_SW_HVS_63 : 8|4@1+ (1,0) [0|15] ""  MBMU,PC
 SG_ ST_PreCharge_SW_HVS_63 : 12|1@1+ (1,0) [0|1] ""  MBMU,PC
 SG_ ST_Main_POS_SW_HVS_63 : 13|1@1+ (1,0) [0|1] ""  MBMU,PC
 SG_ ST_Main_NEG_SW_HVS_63 : 14|1@1+ (1,0) [0|1] ""  MBMU,PC
 SG_ ST_System_63 : 17|1@1+ (1,0) [0|1] ""  MBMU,PC
 SG_ ST_CALIBRATION_63 : 18|1@1+ (1,0) [0|1] ""  MBMU,PC
 SG_ ST_Insulation_63 : 19|2@1+ (1,0) [0|3] ""  MBMU,PC
 SG_ ST_PowerDown_63 : 21|3@1+ (1,0) [0|7] ""  MBMU,PC
 SG_ ST_pwr12V_63 : 24|1@1+ (1,0) [0|1] ""  MBMU,PC
 SG_ ST_pwr5V_63 : 25|1@1+ (1,0) [0|1] ""  MBMU,PC
 SG_ ST_pwr24V_63 : 26|1@1+ (1,0) [0|1] ""  MBMU,PC
 SG_ ST_pwrStatus_63 : 27|3@1+ (1,0) [0|7] ""  MBMU,PC
 SG_ S2A_S2_FullChgFlgFromSBMU_63 : 30|8@1+ (1,0) [0|255] ""  MBMU,PC
 SG_ ST_cscStandby_63 : 46|2@1+ (1,0) [0|3] ""  MBMU,PC
 SG_ ST_OffReasonMsg_63 : 48|16@1+ (1,0) [0|65535] ""  MBMU,PC

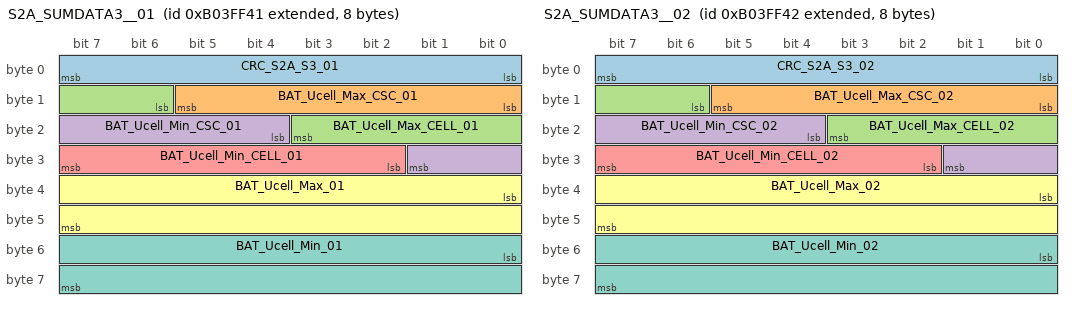
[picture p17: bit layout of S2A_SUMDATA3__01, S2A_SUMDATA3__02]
BO_ 2332294977 S2A_SUMDATA3__01: 8 SBMU
 SG_ CRC_S2A_S3_01 : 0|8@1+ (1,0) [0|255] ""  MBMU,PC
 SG_ BAT_Ucell_Max_CSC_01 : 8|6@1+ (1,0) [0|63] ""  MBMU,PC
 SG_ BAT_Ucell_Max_CELL_01 : 14|6@1+ (1,0) [0|63] ""  MBMU,PC
 SG_ BAT_Ucell_Min_CSC_01 : 20|6@1+ (1,0) [0|63] ""  MBMU,PC
 SG_ BAT_Ucell_Min_CELL_01 : 26|6@1+ (1,0) [0|63] ""  MBMU,PC
 SG_ BAT_Ucell_Max_01 : 32|16@1+ (1,0) [0|65535] "mV"  MBMU,PC
 SG_ BAT_Ucell_Min_01 : 48|16@1+ (1,0) [0|65535] "mV"  MBMU,PC

BO_ 2332294978 S2A_SUMDATA3__02: 8 SBMU
 SG_ CRC_S2A_S3_02 : 0|8@1+ (1,0) [0|255] ""  MBMU,PC
 SG_ BAT_Ucell_Max_CSC_02 : 8|6@1+ (1,0) [0|63] ""  MBMU,PC
 SG_ BAT_Ucell_Max_CELL_02 : 14|6@1+ (1,0) [0|63] ""  MBMU,PC
 SG_ BAT_Ucell_Min_CSC_02 : 20|6@1+ (1,0) [0|63] ""  MBMU,PC
 SG_ BAT_Ucell_Min_CELL_02 : 26|6@1+ (1,0) [0|63] ""  MBMU,PC
 SG_ BAT_Ucell_Max_02 : 32|16@1+ (1,0) [0|65535] "mV"  MBMU,PC
 SG_ BAT_Ucell_Min_02 : 48|16@1+ (1,0) [0|65535] "mV"  MBMU,PC

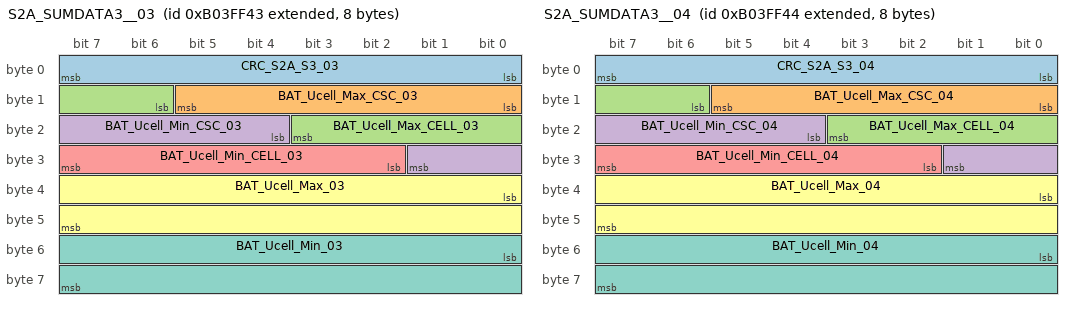
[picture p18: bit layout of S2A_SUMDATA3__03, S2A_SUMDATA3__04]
BO_ 2332294979 S2A_SUMDATA3__03: 8 SBMU
 SG_ CRC_S2A_S3_03 : 0|8@1+ (1,0) [0|255] ""  MBMU,PC
 SG_ BAT_Ucell_Max_CSC_03 : 8|6@1+ (1,0) [0|63] ""  MBMU,PC
 SG_ BAT_Ucell_Max_CELL_03 : 14|6@1+ (1,0) [0|63] ""  MBMU,PC
 SG_ BAT_Ucell_Min_CSC_03 : 20|6@1+ (1,0) [0|63] ""  MBMU,PC
 SG_ BAT_Ucell_Min_CELL_03 : 26|6@1+ (1,0) [0|63] ""  MBMU,PC
 SG_ BAT_Ucell_Max_03 : 32|16@1+ (1,0) [0|65535] "mV"  MBMU,PC
 SG_ BAT_Ucell_Min_03 : 48|16@1+ (1,0) [0|65535] "mV"  MBMU,PC

BO_ 2332294980 S2A_SUMDATA3__04: 8 SBMU
 SG_ CRC_S2A_S3_04 : 0|8@1+ (1,0) [0|255] ""  MBMU,PC
 SG_ BAT_Ucell_Max_CSC_04 : 8|6@1+ (1,0) [0|63] ""  MBMU,PC
 SG_ BAT_Ucell_Max_CELL_04 : 14|6@1+ (1,0) [0|63] ""  MBMU,PC
 SG_ BAT_Ucell_Min_CSC_04 : 20|6@1+ (1,0) [0|63] ""  MBMU,PC
 SG_ BAT_Ucell_Min_CELL_04 : 26|6@1+ (1,0) [0|63] ""  MBMU,PC
 SG_ BAT_Ucell_Max_04 : 32|16@1+ (1,0) [0|65535] "mV"  MBMU,PC
 SG_ BAT_Ucell_Min_04 : 48|16@1+ (1,0) [0|65535] "mV"  MBMU,PC

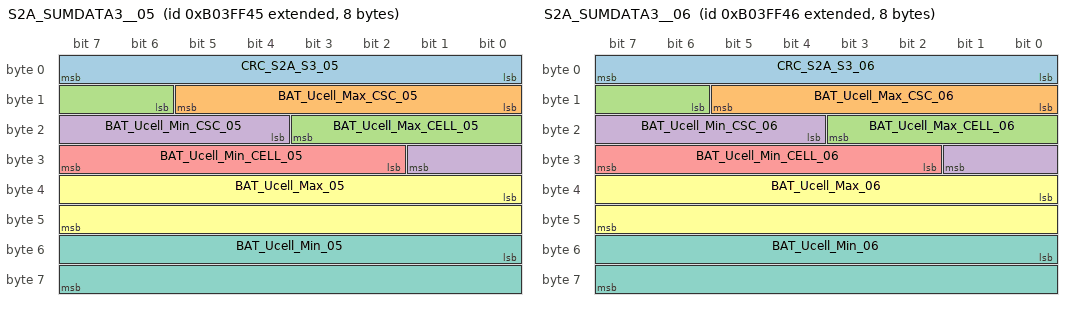
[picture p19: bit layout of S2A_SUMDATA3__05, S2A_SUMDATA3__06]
BO_ 2332294981 S2A_SUMDATA3__05: 8 SBMU
 SG_ CRC_S2A_S3_05 : 0|8@1+ (1,0) [0|255] ""  MBMU,PC
 SG_ BAT_Ucell_Max_CSC_05 : 8|6@1+ (1,0) [0|63] ""  MBMU,PC
 SG_ BAT_Ucell_Max_CELL_05 : 14|6@1+ (1,0) [0|63] ""  MBMU,PC
 SG_ BAT_Ucell_Min_CSC_05 : 20|6@1+ (1,0) [0|63] ""  MBMU,PC
 SG_ BAT_Ucell_Min_CELL_05 : 26|6@1+ (1,0) [0|63] ""  MBMU,PC
 SG_ BAT_Ucell_Max_05 : 32|16@1+ (1,0) [0|65535] "mV"  MBMU,PC
 SG_ BAT_Ucell_Min_05 : 48|16@1+ (1,0) [0|65535] "mV"  MBMU,PC

BO_ 2332294982 S2A_SUMDATA3__06: 8 SBMU
 SG_ CRC_S2A_S3_06 : 0|8@1+ (1,0) [0|255] ""  MBMU,PC
 SG_ BAT_Ucell_Max_CSC_06 : 8|6@1+ (1,0) [0|63] ""  MBMU,PC
 SG_ BAT_Ucell_Max_CELL_06 : 14|6@1+ (1,0) [0|63] ""  MBMU,PC
 SG_ BAT_Ucell_Min_CSC_06 : 20|6@1+ (1,0) [0|63] ""  MBMU,PC
 SG_ BAT_Ucell_Min_CELL_06 : 26|6@1+ (1,0) [0|63] ""  MBMU,PC
 SG_ BAT_Ucell_Max_06 : 32|16@1+ (1,0) [0|65535] "mV"  MBMU,PC
 SG_ BAT_Ucell_Min_06 : 48|16@1+ (1,0) [0|65535] "mV"  MBMU,PC

BO_ 2332294983 S2A_SUMDATA3__07: 8 SBMU
 SG_ CRC_S2A_S3_07 : 0|8@1+ (1,0) [0|255] ""  MBMU,PC
 SG_ BAT_Ucell_Max_CSC_07 : 8|6@1+ (1,0) [0|63] ""  MBMU,PC
 SG_ BAT_Ucell_Max_CELL_07 : 14|6@1+ (1,0) [0|63] ""  MBMU,PC
 SG_ BAT_Ucell_Min_CSC_07 : 20|6@1+ (1,0) [0|63] ""  MBMU,PC
 SG_ BAT_Ucell_Min_CELL_07 : 26|6@1+ (1,0) [0|63] ""  MBMU,PC
 SG_ BAT_Ucell_Max_07 : 32|16@1+ (1,0) [0|65535] "mV"  MBMU,PC
 SG_ BAT_Ucell_Min_07 : 48|16@1+ (1,0) [0|65535] "mV"  MBMU,PC

BO_ 2332294984 S2A_SUMDATA3__08: 8 SBMU
 SG_ CRC_S2A_S3_08 : 0|8@1+ (1,0) [0|255] ""  MBMU,PC
 SG_ BAT_Ucell_Max_CSC_08 : 8|6@1+ (1,0) [0|63] ""  MBMU,PC
 SG_ BAT_Ucell_Max_CELL_08 : 14|6@1+ (1,0) [0|63] ""  MBMU,PC
 SG_ BAT_Ucell_Min_CSC_08 : 20|6@1+ (1,0) [0|63] ""  MBMU,PC
 SG_ BAT_Ucell_Min_CELL_08 : 26|6@1+ (1,0) [0|63] ""  MBMU,PC
 SG_ BAT_Ucell_Max_08 : 32|16@1+ (1,0) [0|65535] "mV"  MBMU,PC
 SG_ BAT_Ucell_Min_08 : 48|16@1+ (1,0) [0|65535] "mV"  MBMU,PC

BO_ 2332294985 S2A_SUMDATA3__09: 8 SBMU
 SG_ CRC_S2A_S3_09 : 0|8@1+ (1,0) [0|255] ""  MBMU,PC
 SG_ BAT_Ucell_Max_CSC_09 : 8|6@1+ (1,0) [0|63] ""  MBMU,PC
 SG_ BAT_Ucell_Max_CELL_09 : 14|6@1+ (1,0) [0|63] ""  MBMU,PC
 SG_ BAT_Ucell_Min_CSC_09 : 20|6@1+ (1,0) [0|63] ""  MBMU,PC
 SG_ BAT_Ucell_Min_CELL_09 : 26|6@1+ (1,0) [0|63] ""  MBMU,PC
 SG_ BAT_Ucell_Max_09 : 32|16@1+ (1,0) [0|65535] "mV"  MBMU,PC
 SG_ BAT_Ucell_Min_09 : 48|16@1+ (1,0) [0|65535] "mV"  MBMU,PC

BO_ 2332294986 S2A_SUMDATA3__10: 8 SBMU
 SG_ CRC_S2A_S3_10 : 0|8@1+ (1,0) [0|255] ""  MBMU,PC
 SG_ BAT_Ucell_Max_CSC_10 : 8|6@1+ (1,0) [0|63] ""  MBMU,PC
 SG_ BAT_Ucell_Max_CELL_10 : 14|6@1+ (1,0) [0|63] ""  MBMU,PC
 SG_ BAT_Ucell_Min_CSC_10 : 20|6@1+ (1,0) [0|63] ""  MBMU,PC
 SG_ BAT_Ucell_Min_CELL_10 : 26|6@1+ (1,0) [0|63] ""  MBMU,PC
 SG_ BAT_Ucell_Max_10 : 32|16@1+ (1,0) [0|65535] "mV"  MBMU,PC
 SG_ BAT_Ucell_Min_10 : 48|16@1+ (1,0) [0|65535] "mV"  MBMU,PC

BO_ 2332294987 S2A_SUMDATA3__11: 8 SBMU
 SG_ CRC_S2A_S3_11 : 0|8@1+ (1,0) [0|255] ""  MBMU,PC
 SG_ BAT_Ucell_Max_CSC_11 : 8|6@1+ (1,0) [0|63] ""  MBMU,PC
 SG_ BAT_Ucell_Max_CELL_11 : 14|6@1+ (1,0) [0|63] ""  MBMU,PC
 SG_ BAT_Ucell_Min_CSC_11 : 20|6@1+ (1,0) [0|63] ""  MBMU,PC
 SG_ BAT_Ucell_Min_CELL_11 : 26|6@1+ (1,0) [0|63] ""  MBMU,PC
 SG_ BAT_Ucell_Max_11 : 32|16@1+ (1,0) [0|65535] "mV"  MBMU,PC
 SG_ BAT_Ucell_Min_11 : 48|16@1+ (1,0) [0|65535] "mV"  MBMU,PC

BO_ 2332294988 S2A_SUMDATA3__12: 8 SBMU
 SG_ CRC_S2A_S3_12 : 0|8@1+ (1,0) [0|255] ""  MBMU,PC
 SG_ BAT_Ucell_Max_CSC_12 : 8|6@1+ (1,0) [0|63] ""  MBMU,PC
 SG_ BAT_Ucell_Max_CELL_12 : 14|6@1+ (1,0) [0|63] ""  MBMU,PC
 SG_ BAT_Ucell_Min_CSC_12 : 20|6@1+ (1,0) [0|63] ""  MBMU,PC
 SG_ BAT_Ucell_Min_CELL_12 : 26|6@1+ (1,0) [0|63] ""  MBMU,PC
 SG_ BAT_Ucell_Max_12 : 32|16@1+ (1,0) [0|65535] "mV"  MBMU,PC
 SG_ BAT_Ucell_Min_12 : 48|16@1+ (1,0) [0|65535] "mV"  MBMU,PC

BO_ 2332294989 S2A_SUMDATA3__13: 8 SBMU
 SG_ CRC_S2A_S3_13 : 0|8@1+ (1,0) [0|255] ""  MBMU,PC
 SG_ BAT_Ucell_Max_CSC_13 : 8|6@1+ (1,0) [0|63] ""  MBMU,PC
 SG_ BAT_Ucell_Max_CELL_13 : 14|6@1+ (1,0) [0|63] ""  MBMU,PC
 SG_ BAT_Ucell_Min_CSC_13 : 20|6@1+ (1,0) [0|63] ""  MBMU,PC
 SG_ BAT_Ucell_Min_CELL_13 : 26|6@1+ (1,0) [0|63] ""  MBMU,PC
 SG_ BAT_Ucell_Max_13 : 32|16@1+ (1,0) [0|65535] "mV"  MBMU,PC
 SG_ BAT_Ucell_Min_13 : 48|16@1+ (1,0) [0|65535] "mV"  MBMU,PC

BO_ 2332294990 S2A_SUMDATA3__14: 8 SBMU
 SG_ CRC_S2A_S3_14 : 0|8@1+ (1,0) [0|255] ""  MBMU,PC
 SG_ BAT_Ucell_Max_CSC_14 : 8|6@1+ (1,0) [0|63] ""  MBMU,PC
 SG_ BAT_Ucell_Max_CELL_14 : 14|6@1+ (1,0) [0|63] ""  MBMU,PC
 SG_ BAT_Ucell_Min_CSC_14 : 20|6@1+ (1,0) [0|63] ""  MBMU,PC
 SG_ BAT_Ucell_Min_CELL_14 : 26|6@1+ (1,0) [0|63] ""  MBMU,PC
 SG_ BAT_Ucell_Max_14 : 32|16@1+ (1,0) [0|65535] "mV"  MBMU,PC
 SG_ BAT_Ucell_Min_14 : 48|16@1+ (1,0) [0|65535] "mV"  MBMU,PC

BO_ 2332294991 S2A_SUMDATA3__15: 8 SBMU
 SG_ CRC_S2A_S3_15 : 0|8@1+ (1,0) [0|255] ""  MBMU,PC
 SG_ BAT_Ucell_Max_CSC_15 : 8|6@1+ (1,0) [0|63] ""  MBMU,PC
 SG_ BAT_Ucell_Max_CELL_15 : 14|6@1+ (1,0) [0|63] ""  MBMU,PC
 SG_ BAT_Ucell_Min_CSC_15 : 20|6@1+ (1,0) [0|63] ""  MBMU,PC
 SG_ BAT_Ucell_Min_CELL_15 : 26|6@1+ (1,0) [0|63] ""  MBMU,PC
 SG_ BAT_Ucell_Max_15 : 32|16@1+ (1,0) [0|65535] "mV"  MBMU,PC
 SG_ BAT_Ucell_Min_15 : 48|16@1+ (1,0) [0|65535] "mV"  MBMU,PC

BO_ 2332294992 S2A_SUMDATA3__16: 8 SBMU
 SG_ CRC_S2A_S3_16 : 0|8@1+ (1,0) [0|255] ""  MBMU,PC
 SG_ BAT_Ucell_Max_CSC_16 : 8|6@1+ (1,0) [0|63] ""  MBMU,PC
 SG_ BAT_Ucell_Max_CELL_16 : 14|6@1+ (1,0) [0|63] ""  MBMU,PC
 SG_ BAT_Ucell_Min_CSC_16 : 20|6@1+ (1,0) [0|63] ""  MBMU,PC
 SG_ BAT_Ucell_Min_CELL_16 : 26|6@1+ (1,0) [0|63] ""  MBMU,PC
 SG_ BAT_Ucell_Max_16 : 32|16@1+ (1,0) [0|65535] "mV"  MBMU,PC
 SG_ BAT_Ucell_Min_16 : 48|16@1+ (1,0) [0|65535] "mV"  MBMU,PC

BO_ 2332294993 S2A_SUMDATA3__17: 8 SBMU
 SG_ CRC_S2A_S3_17 : 0|8@1+ (1,0) [0|255] ""  MBMU,PC
 SG_ BAT_Ucell_Max_CSC_17 : 8|6@1+ (1,0) [0|63] ""  MBMU,PC
 SG_ BAT_Ucell_Max_CELL_17 : 14|6@1+ (1,0) [0|63] ""  MBMU,PC
 SG_ BAT_Ucell_Min_CSC_17 : 20|6@1+ (1,0) [0|63] ""  MBMU,PC
 SG_ BAT_Ucell_Min_CELL_17 : 26|6@1+ (1,0) [0|63] ""  MBMU,PC
 SG_ BAT_Ucell_Max_17 : 32|16@1+ (1,0) [0|65535] "mV"  MBMU,PC
 SG_ BAT_Ucell_Min_17 : 48|16@1+ (1,0) [0|65535] "mV"  MBMU,PC

BO_ 2332294994 S2A_SUMDATA3__18: 8 SBMU
 SG_ CRC_S2A_S3_18 : 0|8@1+ (1,0) [0|255] ""  MBMU,PC
 SG_ BAT_Ucell_Max_CSC_18 : 8|6@1+ (1,0) [0|63] ""  MBMU,PC
 SG_ BAT_Ucell_Max_CELL_18 : 14|6@1+ (1,0) [0|63] ""  MBMU,PC
 SG_ BAT_Ucell_Min_CSC_18 : 20|6@1+ (1,0) [0|63] ""  MBMU,PC
 SG_ BAT_Ucell_Min_CELL_18 : 26|6@1+ (1,0) [0|63] ""  MBMU,PC
 SG_ BAT_Ucell_Max_18 : 32|16@1+ (1,0) [0|65535] "mV"  MBMU,PC
 SG_ BAT_Ucell_Min_18 : 48|16@1+ (1,0) [0|65535] "mV"  MBMU,PC

BO_ 2332294995 S2A_SUMDATA3__19: 8 SBMU
 SG_ CRC_S2A_S3_19 : 0|8@1+ (1,0) [0|255] ""  MBMU,PC
 SG_ BAT_Ucell_Max_CSC_19 : 8|6@1+ (1,0) [0|63] ""  MBMU,PC
 SG_ BAT_Ucell_Max_CELL_19 : 14|6@1+ (1,0) [0|63] ""  MBMU,PC
 SG_ BAT_Ucell_Min_CSC_19 : 20|6@1+ (1,0) [0|63] ""  MBMU,PC
 SG_ BAT_Ucell_Min_CELL_19 : 26|6@1+ (1,0) [0|63] ""  MBMU,PC
 SG_ BAT_Ucell_Max_19 : 32|16@1+ (1,0) [0|65535] "mV"  MBMU,PC
 SG_ BAT_Ucell_Min_19 : 48|16@1+ (1,0) [0|65535] "mV"  MBMU,PC

BO_ 2332294996 S2A_SUMDATA3__20: 8 SBMU
 SG_ CRC_S2A_S3_20 : 0|8@1+ (1,0) [0|255] ""  MBMU,PC
 SG_ BAT_Ucell_Max_CSC_20 : 8|6@1+ (1,0) [0|63] ""  MBMU,PC
 SG_ BAT_Ucell_Max_CELL_20 : 14|6@1+ (1,0) [0|63] ""  MBMU,PC
 SG_ BAT_Ucell_Min_CSC_20 : 20|6@1+ (1,0) [0|63] ""  MBMU,PC
 SG_ BAT_Ucell_Min_CELL_20 : 26|6@1+ (1,0) [0|63] ""  MBMU,PC
 SG_ BAT_Ucell_Max_20 : 32|16@1+ (1,0) [0|65535] "mV"  MBMU,PC
 SG_ BAT_Ucell_Min_20 : 48|16@1+ (1,0) [0|65535] "mV"  MBMU,PC

BO_ 2332294997 S2A_SUMDATA3__21: 8 SBMU
 SG_ CRC_S2A_S3_21 : 0|8@1+ (1,0) [0|255] ""  MBMU,PC
 SG_ BAT_Ucell_Max_CSC_21 : 8|6@1+ (1,0) [0|63] ""  MBMU,PC
 SG_ BAT_Ucell_Max_CELL_21 : 14|6@1+ (1,0) [0|63] ""  MBMU,PC
 SG_ BAT_Ucell_Min_CSC_21 : 20|6@1+ (1,0) [0|63] ""  MBMU,PC
 SG_ BAT_Ucell_Min_CELL_21 : 26|6@1+ (1,0) [0|63] ""  MBMU,PC
 SG_ BAT_Ucell_Max_21 : 32|16@1+ (1,0) [0|65535] "mV"  MBMU,PC
 SG_ BAT_Ucell_Min_21 : 48|16@1+ (1,0) [0|65535] "mV"  MBMU,PC

BO_ 2332294998 S2A_SUMDATA3__22: 8 SBMU
 SG_ CRC_S2A_S3_22 : 0|8@1+ (1,0) [0|255] ""  MBMU,PC
 SG_ BAT_Ucell_Max_CSC_22 : 8|6@1+ (1,0) [0|63] ""  MBMU,PC
 SG_ BAT_Ucell_Max_CELL_22 : 14|6@1+ (1,0) [0|63] ""  MBMU,PC
 SG_ BAT_Ucell_Min_CSC_22 : 20|6@1+ (1,0) [0|63] ""  MBMU,PC
 SG_ BAT_Ucell_Min_CELL_22 : 26|6@1+ (1,0) [0|63] ""  MBMU,PC
 SG_ BAT_Ucell_Max_22 : 32|16@1+ (1,0) [0|65535] "mV"  MBMU,PC
 SG_ BAT_Ucell_Min_22 : 48|16@1+ (1,0) [0|65535] "mV"  MBMU,PC

BO_ 2332294999 S2A_SUMDATA3__23: 8 SBMU
 SG_ CRC_S2A_S3_23 : 0|8@1+ (1,0) [0|255] ""  MBMU,PC
 SG_ BAT_Ucell_Max_CSC_23 : 8|6@1+ (1,0) [0|63] ""  MBMU,PC
 SG_ BAT_Ucell_Max_CELL_23 : 14|6@1+ (1,0) [0|63] ""  MBMU,PC
 SG_ BAT_Ucell_Min_CSC_23 : 20|6@1+ (1,0) [0|63] ""  MBMU,PC
 SG_ BAT_Ucell_Min_CELL_23 : 26|6@1+ (1,0) [0|63] ""  MBMU,PC
 SG_ BAT_Ucell_Max_23 : 32|16@1+ (1,0) [0|65535] "mV"  MBMU,PC
 SG_ BAT_Ucell_Min_23 : 48|16@1+ (1,0) [0|65535] "mV"  MBMU,PC

BO_ 2332295000 S2A_SUMDATA3__24: 8 SBMU
 SG_ CRC_S2A_S3_24 : 0|8@1+ (1,0) [0|255] ""  MBMU,PC
 SG_ BAT_Ucell_Max_CSC_24 : 8|6@1+ (1,0) [0|63] ""  MBMU,PC
 SG_ BAT_Ucell_Max_CELL_24 : 14|6@1+ (1,0) [0|63] ""  MBMU,PC
 SG_ BAT_Ucell_Min_CSC_24 : 20|6@1+ (1,0) [0|63] ""  MBMU,PC
 SG_ BAT_Ucell_Min_CELL_24 : 26|6@1+ (1,0) [0|63] ""  MBMU,PC
 SG_ BAT_Ucell_Max_24 : 32|16@1+ (1,0) [0|65535] "mV"  MBMU,PC
 SG_ BAT_Ucell_Min_24 : 48|16@1+ (1,0) [0|65535] "mV"  MBMU,PC

BO_ 2332295001 S2A_SUMDATA3__25: 8 SBMU
 SG_ CRC_S2A_S3_25 : 0|8@1+ (1,0) [0|255] ""  MBMU,PC
 SG_ BAT_Ucell_Max_CSC_25 : 8|6@1+ (1,0) [0|63] ""  MBMU,PC
 SG_ BAT_Ucell_Max_CELL_25 : 14|6@1+ (1,0) [0|63] ""  MBMU,PC
 SG_ BAT_Ucell_Min_CSC_25 : 20|6@1+ (1,0) [0|63] ""  MBMU,PC
 SG_ BAT_Ucell_Min_CELL_25 : 26|6@1+ (1,0) [0|63] ""  MBMU,PC
 SG_ BAT_Ucell_Max_25 : 32|16@1+ (1,0) [0|65535] "mV"  MBMU,PC
 SG_ BAT_Ucell_Min_25 : 48|16@1+ (1,0) [0|65535] "mV"  MBMU,PC

BO_ 2332295002 S2A_SUMDATA3__26: 8 SBMU
 SG_ CRC_S2A_S3_26 : 0|8@1+ (1,0) [0|255] ""  MBMU,PC
 SG_ BAT_Ucell_Max_CSC_26 : 8|6@1+ (1,0) [0|63] ""  MBMU,PC
 SG_ BAT_Ucell_Max_CELL_26 : 14|6@1+ (1,0) [0|63] ""  MBMU,PC
 SG_ BAT_Ucell_Min_CSC_26 : 20|6@1+ (1,0) [0|63] ""  MBMU,PC
 SG_ BAT_Ucell_Min_CELL_26 : 26|6@1+ (1,0) [0|63] ""  MBMU,PC
 SG_ BAT_Ucell_Max_26 : 32|16@1+ (1,0) [0|65535] "mV"  MBMU,PC
 SG_ BAT_Ucell_Min_26 : 48|16@1+ (1,0) [0|65535] "mV"  MBMU,PC

BO_ 2332295003 S2A_SUMDATA3__27: 8 SBMU
 SG_ CRC_S2A_S3_27 : 0|8@1+ (1,0) [0|255] ""  MBMU,PC
 SG_ BAT_Ucell_Max_CSC_27 : 8|6@1+ (1,0) [0|63] ""  MBMU,PC
 SG_ BAT_Ucell_Max_CELL_27 : 14|6@1+ (1,0) [0|63] ""  MBMU,PC
 SG_ BAT_Ucell_Min_CSC_27 : 20|6@1+ (1,0) [0|63] ""  MBMU,PC
 SG_ BAT_Ucell_Min_CELL_27 : 26|6@1+ (1,0) [0|63] ""  MBMU,PC
 SG_ BAT_Ucell_Max_27 : 32|16@1+ (1,0) [0|65535] "mV"  MBMU,PC
 SG_ BAT_Ucell_Min_27 : 48|16@1+ (1,0) [0|65535] "mV"  MBMU,PC

BO_ 2332295004 S2A_SUMDATA3__28: 8 SBMU
 SG_ CRC_S2A_S3_28 : 0|8@1+ (1,0) [0|255] ""  MBMU,PC
 SG_ BAT_Ucell_Max_CSC_28 : 8|6@1+ (1,0) [0|63] ""  MBMU,PC
 SG_ BAT_Ucell_Max_CELL_28 : 14|6@1+ (1,0) [0|63] ""  MBMU,PC
 SG_ BAT_Ucell_Min_CSC_28 : 20|6@1+ (1,0) [0|63] ""  MBMU,PC
 SG_ BAT_Ucell_Min_CELL_28 : 26|6@1+ (1,0) [0|63] ""  MBMU,PC
 SG_ BAT_Ucell_Max_28 : 32|16@1+ (1,0) [0|65535] "mV"  MBMU,PC
 SG_ BAT_Ucell_Min_28 : 48|16@1+ (1,0) [0|65535] "mV"  MBMU,PC

BO_ 2332295005 S2A_SUMDATA3__29: 8 SBMU
 SG_ CRC_S2A_S3_29 : 0|8@1+ (1,0) [0|255] ""  MBMU,PC
 SG_ BAT_Ucell_Max_CSC_29 : 8|6@1+ (1,0) [0|63] ""  MBMU,PC
 SG_ BAT_Ucell_Max_CELL_29 : 14|6@1+ (1,0) [0|63] ""  MBMU,PC
 SG_ BAT_Ucell_Min_CSC_29 : 20|6@1+ (1,0) [0|63] ""  MBMU,PC
 SG_ BAT_Ucell_Min_CELL_29 : 26|6@1+ (1,0) [0|63] ""  MBMU,PC
 SG_ BAT_Ucell_Max_29 : 32|16@1+ (1,0) [0|65535] "mV"  MBMU,PC
 SG_ BAT_Ucell_Min_29 : 48|16@1+ (1,0) [0|65535] "mV"  MBMU,PC

BO_ 2332295006 S2A_SUMDATA3__30: 8 SBMU
 SG_ CRC_S2A_S3_30 : 0|8@1+ (1,0) [0|255] ""  MBMU,PC
 SG_ BAT_Ucell_Max_CSC_30 : 8|6@1+ (1,0) [0|63] ""  MBMU,PC
 SG_ BAT_Ucell_Max_CELL_30 : 14|6@1+ (1,0) [0|63] ""  MBMU,PC
 SG_ BAT_Ucell_Min_CSC_30 : 20|6@1+ (1,0) [0|63] ""  MBMU,PC
 SG_ BAT_Ucell_Min_CELL_30 : 26|6@1+ (1,0) [0|63] ""  MBMU,PC
 SG_ BAT_Ucell_Max_30 : 32|16@1+ (1,0) [0|65535] "mV"  MBMU,PC
 SG_ BAT_Ucell_Min_30 : 48|16@1+ (1,0) [0|65535] "mV"  MBMU,PC

BO_ 2332295007 S2A_SUMDATA3__31: 8 SBMU
 SG_ CRC_S2A_S3_31 : 0|8@1+ (1,0) [0|255] ""  MBMU,PC
 SG_ BAT_Ucell_Max_CSC_31 : 8|6@1+ (1,0) [0|63] ""  MBMU,PC
 SG_ BAT_Ucell_Max_CELL_31 : 14|6@1+ (1,0) [0|63] ""  MBMU,PC
 SG_ BAT_Ucell_Min_CSC_31 : 20|6@1+ (1,0) [0|63] ""  MBMU,PC
 SG_ BAT_Ucell_Min_CELL_31 : 26|6@1+ (1,0) [0|63] ""  MBMU,PC
 SG_ BAT_Ucell_Max_31 : 32|16@1+ (1,0) [0|65535] "mV"  MBMU,PC
 SG_ BAT_Ucell_Min_31 : 48|16@1+ (1,0) [0|65535] "mV"  MBMU,PC

BO_ 2332295008 S2A_SUMDATA3__32: 8 SBMU
 SG_ CRC_S2A_S3_32 : 0|8@1+ (1,0) [0|255] ""  MBMU,PC
 SG_ BAT_Ucell_Max_CSC_32 : 8|6@1+ (1,0) [0|63] ""  MBMU,PC
 SG_ BAT_Ucell_Max_CELL_32 : 14|6@1+ (1,0) [0|63] ""  MBMU,PC
 SG_ BAT_Ucell_Min_CSC_32 : 20|6@1+ (1,0) [0|63] ""  MBMU,PC
 SG_ BAT_Ucell_Min_CELL_32 : 26|6@1+ (1,0) [0|63] ""  MBMU,PC
 SG_ BAT_Ucell_Max_32 : 32|16@1+ (1,0) [0|65535] "mV"  MBMU,PC
 SG_ BAT_Ucell_Min_32 : 48|16@1+ (1,0) [0|65535] "mV"  MBMU,PC

BO_ 2332295009 S2A_SUMDATA3__33: 8 SBMU
 SG_ CRC_S2A_S3_33 : 0|8@1+ (1,0) [0|255] ""  MBMU,PC
 SG_ BAT_Ucell_Max_CSC_33 : 8|6@1+ (1,0) [0|63] ""  MBMU,PC
 SG_ BAT_Ucell_Max_CELL_33 : 14|6@1+ (1,0) [0|63] ""  MBMU,PC
 SG_ BAT_Ucell_Min_CSC_33 : 20|6@1+ (1,0) [0|63] ""  MBMU,PC
 SG_ BAT_Ucell_Min_CELL_33 : 26|6@1+ (1,0) [0|63] ""  MBMU,PC
 SG_ BAT_Ucell_Max_33 : 32|16@1+ (1,0) [0|65535] "mV"  MBMU,PC
 SG_ BAT_Ucell_Min_33 : 48|16@1+ (1,0) [0|65535] "mV"  MBMU,PC

BO_ 2332295010 S2A_SUMDATA3__34: 8 SBMU
 SG_ CRC_S2A_S3_34 : 0|8@1+ (1,0) [0|255] ""  MBMU,PC
 SG_ BAT_Ucell_Max_CSC_34 : 8|6@1+ (1,0) [0|63] ""  MBMU,PC
 SG_ BAT_Ucell_Max_CELL_34 : 14|6@1+ (1,0) [0|63] ""  MBMU,PC
 SG_ BAT_Ucell_Min_CSC_34 : 20|6@1+ (1,0) [0|63] ""  MBMU,PC
 SG_ BAT_Ucell_Min_CELL_34 : 26|6@1+ (1,0) [0|63] ""  MBMU,PC
 SG_ BAT_Ucell_Max_34 : 32|16@1+ (1,0) [0|65535] "mV"  MBMU,PC
 SG_ BAT_Ucell_Min_34 : 48|16@1+ (1,0) [0|65535] "mV"  MBMU,PC

BO_ 2332295011 S2A_SUMDATA3__35: 8 SBMU
 SG_ CRC_S2A_S3_35 : 0|8@1+ (1,0) [0|255] ""  MBMU,PC
 SG_ BAT_Ucell_Max_CSC_35 : 8|6@1+ (1,0) [0|63] ""  MBMU,PC
 SG_ BAT_Ucell_Max_CELL_35 : 14|6@1+ (1,0) [0|63] ""  MBMU,PC
 SG_ BAT_Ucell_Min_CSC_35 : 20|6@1+ (1,0) [0|63] ""  MBMU,PC
 SG_ BAT_Ucell_Min_CELL_35 : 26|6@1+ (1,0) [0|63] ""  MBMU,PC
 SG_ BAT_Ucell_Max_35 : 32|16@1+ (1,0) [0|65535] "mV"  MBMU,PC
 SG_ BAT_Ucell_Min_35 : 48|16@1+ (1,0) [0|65535] "mV"  MBMU,PC

BO_ 2332295012 S2A_SUMDATA3__36: 8 SBMU
 SG_ CRC_S2A_S3_36 : 0|8@1+ (1,0) [0|255] ""  MBMU,PC
 SG_ BAT_Ucell_Max_CSC_36 : 8|6@1+ (1,0) [0|63] ""  MBMU,PC
 SG_ BAT_Ucell_Max_CELL_36 : 14|6@1+ (1,0) [0|63] ""  MBMU,PC
 SG_ BAT_Ucell_Min_CSC_36 : 20|6@1+ (1,0) [0|63] ""  MBMU,PC
 SG_ BAT_Ucell_Min_CELL_36 : 26|6@1+ (1,0) [0|63] ""  MBMU,PC
 SG_ BAT_Ucell_Max_36 : 32|16@1+ (1,0) [0|65535] "mV"  MBMU,PC
 SG_ BAT_Ucell_Min_36 : 48|16@1+ (1,0) [0|65535] "mV"  MBMU,PC

BO_ 2332295013 S2A_SUMDATA3__37: 8 SBMU
 SG_ CRC_S2A_S3_37 : 0|8@1+ (1,0) [0|255] ""  MBMU,PC
 SG_ BAT_Ucell_Max_CSC_37 : 8|6@1+ (1,0) [0|63] ""  MBMU,PC
 SG_ BAT_Ucell_Max_CELL_37 : 14|6@1+ (1,0) [0|63] ""  MBMU,PC
 SG_ BAT_Ucell_Min_CSC_37 : 20|6@1+ (1,0) [0|63] ""  MBMU,PC
 SG_ BAT_Ucell_Min_CELL_37 : 26|6@1+ (1,0) [0|63] ""  MBMU,PC
 SG_ BAT_Ucell_Max_37 : 32|16@1+ (1,0) [0|65535] "mV"  MBMU,PC
 SG_ BAT_Ucell_Min_37 : 48|16@1+ (1,0) [0|65535] "mV"  MBMU,PC

BO_ 2332295014 S2A_SUMDATA3__38: 8 SBMU
 SG_ CRC_S2A_S3_38 : 0|8@1+ (1,0) [0|255] ""  MBMU,PC
 SG_ BAT_Ucell_Max_CSC_38 : 8|6@1+ (1,0) [0|63] ""  MBMU,PC
 SG_ BAT_Ucell_Max_CELL_38 : 14|6@1+ (1,0) [0|63] ""  MBMU,PC
 SG_ BAT_Ucell_Min_CSC_38 : 20|6@1+ (1,0) [0|63] ""  MBMU,PC
 SG_ BAT_Ucell_Min_CELL_38 : 26|6@1+ (1,0) [0|63] ""  MBMU,PC
 SG_ BAT_Ucell_Max_38 : 32|16@1+ (1,0) [0|65535] "mV"  MBMU,PC
 SG_ BAT_Ucell_Min_38 : 48|16@1+ (1,0) [0|65535] "mV"  MBMU,PC

BO_ 2332295015 S2A_SUMDATA3__39: 8 SBMU
 SG_ CRC_S2A_S3_39 : 0|8@1+ (1,0) [0|255] ""  MBMU,PC
 SG_ BAT_Ucell_Max_CSC_39 : 8|6@1+ (1,0) [0|63] ""  MBMU,PC
 SG_ BAT_Ucell_Max_CELL_39 : 14|6@1+ (1,0) [0|63] ""  MBMU,PC
 SG_ BAT_Ucell_Min_CSC_39 : 20|6@1+ (1,0) [0|63] ""  MBMU,PC
 SG_ BAT_Ucell_Min_CELL_39 : 26|6@1+ (1,0) [0|63] ""  MBMU,PC
 SG_ BAT_Ucell_Max_39 : 32|16@1+ (1,0) [0|65535] "mV"  MBMU,PC
 SG_ BAT_Ucell_Min_39 : 48|16@1+ (1,0) [0|65535] "mV"  MBMU,PC

BO_ 2332295016 S2A_SUMDATA3__40: 8 SBMU
 SG_ CRC_S2A_S3_40 : 0|8@1+ (1,0) [0|255] ""  MBMU,PC
 SG_ BAT_Ucell_Max_CSC_40 : 8|6@1+ (1,0) [0|63] ""  MBMU,PC
 SG_ BAT_Ucell_Max_CELL_40 : 14|6@1+ (1,0) [0|63] ""  MBMU,PC
 SG_ BAT_Ucell_Min_CSC_40 : 20|6@1+ (1,0) [0|63] ""  MBMU,PC
 SG_ BAT_Ucell_Min_CELL_40 : 26|6@1+ (1,0) [0|63] ""  MBMU,PC
 SG_ BAT_Ucell_Max_40 : 32|16@1+ (1,0) [0|65535] "mV"  MBMU,PC
 SG_ BAT_Ucell_Min_40 : 48|16@1+ (1,0) [0|65535] "mV"  MBMU,PC

BO_ 2332295017 S2A_SUMDATA3__41: 8 SBMU
 SG_ CRC_S2A_S3_41 : 0|8@1+ (1,0) [0|255] ""  MBMU,PC
 SG_ BAT_Ucell_Max_CSC_41 : 8|6@1+ (1,0) [0|63] ""  MBMU,PC
 SG_ BAT_Ucell_Max_CELL_41 : 14|6@1+ (1,0) [0|63] ""  MBMU,PC
 SG_ BAT_Ucell_Min_CSC_41 : 20|6@1+ (1,0) [0|63] ""  MBMU,PC
 SG_ BAT_Ucell_Min_CELL_41 : 26|6@1+ (1,0) [0|63] ""  MBMU,PC
 SG_ BAT_Ucell_Max_41 : 32|16@1+ (1,0) [0|65535] "mV"  MBMU,PC
 SG_ BAT_Ucell_Min_41 : 48|16@1+ (1,0) [0|65535] "mV"  MBMU,PC

BO_ 2332295018 S2A_SUMDATA3__42: 8 SBMU
 SG_ CRC_S2A_S3_42 : 0|8@1+ (1,0) [0|255] ""  MBMU,PC
 SG_ BAT_Ucell_Max_CSC_42 : 8|6@1+ (1,0) [0|63] ""  MBMU,PC
 SG_ BAT_Ucell_Max_CELL_42 : 14|6@1+ (1,0) [0|63] ""  MBMU,PC
 SG_ BAT_Ucell_Min_CSC_42 : 20|6@1+ (1,0) [0|63] ""  MBMU,PC
 SG_ BAT_Ucell_Min_CELL_42 : 26|6@1+ (1,0) [0|63] ""  MBMU,PC
 SG_ BAT_Ucell_Max_42 : 32|16@1+ (1,0) [0|65535] "mV"  MBMU,PC
 SG_ BAT_Ucell_Min_42 : 48|16@1+ (1,0) [0|65535] "mV"  MBMU,PC

BO_ 2332295019 S2A_SUMDATA3__43: 8 SBMU
 SG_ CRC_S2A_S3_43 : 0|8@1+ (1,0) [0|255] ""  MBMU,PC
 SG_ BAT_Ucell_Max_CSC_43 : 8|6@1+ (1,0) [0|63] ""  MBMU,PC
 SG_ BAT_Ucell_Max_CELL_43 : 14|6@1+ (1,0) [0|63] ""  MBMU,PC
 SG_ BAT_Ucell_Min_CSC_43 : 20|6@1+ (1,0) [0|63] ""  MBMU,PC
 SG_ BAT_Ucell_Min_CELL_43 : 26|6@1+ (1,0) [0|63] ""  MBMU,PC
 SG_ BAT_Ucell_Max_43 : 32|16@1+ (1,0) [0|65535] "mV"  MBMU,PC
 SG_ BAT_Ucell_Min_43 : 48|16@1+ (1,0) [0|65535] "mV"  MBMU,PC

BO_ 2332295020 S2A_SUMDATA3__44: 8 SBMU
 SG_ CRC_S2A_S3_44 : 0|8@1+ (1,0) [0|255] ""  MBMU,PC
 SG_ BAT_Ucell_Max_CSC_44 : 8|6@1+ (1,0) [0|63] ""  MBMU,PC
 SG_ BAT_Ucell_Max_CELL_44 : 14|6@1+ (1,0) [0|63] ""  MBMU,PC
 SG_ BAT_Ucell_Min_CSC_44 : 20|6@1+ (1,0) [0|63] ""  MBMU,PC
 SG_ BAT_Ucell_Min_CELL_44 : 26|6@1+ (1,0) [0|63] ""  MBMU,PC
 SG_ BAT_Ucell_Max_44 : 32|16@1+ (1,0) [0|65535] "mV"  MBMU,PC
 SG_ BAT_Ucell_Min_44 : 48|16@1+ (1,0) [0|65535] "mV"  MBMU,PC

BO_ 2332295021 S2A_SUMDATA3__45: 8 SBMU
 SG_ CRC_S2A_S3_45 : 0|8@1+ (1,0) [0|255] ""  MBMU,PC
 SG_ BAT_Ucell_Max_CSC_45 : 8|6@1+ (1,0) [0|63] ""  MBMU,PC
 SG_ BAT_Ucell_Max_CELL_45 : 14|6@1+ (1,0) [0|63] ""  MBMU,PC
 SG_ BAT_Ucell_Min_CSC_45 : 20|6@1+ (1,0) [0|63] ""  MBMU,PC
 SG_ BAT_Ucell_Min_CELL_45 : 26|6@1+ (1,0) [0|63] ""  MBMU,PC
 SG_ BAT_Ucell_Max_45 : 32|16@1+ (1,0) [0|65535] "mV"  MBMU,PC
 SG_ BAT_Ucell_Min_45 : 48|16@1+ (1,0) [0|65535] "mV"  MBMU,PC

BO_ 2332295022 S2A_SUMDATA3__46: 8 SBMU
 SG_ CRC_S2A_S3_46 : 0|8@1+ (1,0) [0|255] ""  MBMU,PC
 SG_ BAT_Ucell_Max_CSC_46 : 8|6@1+ (1,0) [0|63] ""  MBMU,PC
 SG_ BAT_Ucell_Max_CELL_46 : 14|6@1+ (1,0) [0|63] ""  MBMU,PC
 SG_ BAT_Ucell_Min_CSC_46 : 20|6@1+ (1,0) [0|63] ""  MBMU,PC
 SG_ BAT_Ucell_Min_CELL_46 : 26|6@1+ (1,0) [0|63] ""  MBMU,PC
 SG_ BAT_Ucell_Max_46 : 32|16@1+ (1,0) [0|65535] "mV"  MBMU,PC
 SG_ BAT_Ucell_Min_46 : 48|16@1+ (1,0) [0|65535] "mV"  MBMU,PC

BO_ 2332295023 S2A_SUMDATA3__47: 8 SBMU
 SG_ CRC_S2A_S3_47 : 0|8@1+ (1,0) [0|255] ""  MBMU,PC
 SG_ BAT_Ucell_Max_CSC_47 : 8|6@1+ (1,0) [0|63] ""  MBMU,PC
 SG_ BAT_Ucell_Max_CELL_47 : 14|6@1+ (1,0) [0|63] ""  MBMU,PC
 SG_ BAT_Ucell_Min_CSC_47 : 20|6@1+ (1,0) [0|63] ""  MBMU,PC
 SG_ BAT_Ucell_Min_CELL_47 : 26|6@1+ (1,0) [0|63] ""  MBMU,PC
 SG_ BAT_Ucell_Max_47 : 32|16@1+ (1,0) [0|65535] "mV"  MBMU,PC
 SG_ BAT_Ucell_Min_47 : 48|16@1+ (1,0) [0|65535] "mV"  MBMU,PC

BO_ 2332295024 S2A_SUMDATA3__48: 8 SBMU
 SG_ CRC_S2A_S3_48 : 0|8@1+ (1,0) [0|255] ""  MBMU,PC
 SG_ BAT_Ucell_Max_CSC_48 : 8|6@1+ (1,0) [0|63] ""  MBMU,PC
 SG_ BAT_Ucell_Max_CELL_48 : 14|6@1+ (1,0) [0|63] ""  MBMU,PC
 SG_ BAT_Ucell_Min_CSC_48 : 20|6@1+ (1,0) [0|63] ""  MBMU,PC
 SG_ BAT_Ucell_Min_CELL_48 : 26|6@1+ (1,0) [0|63] ""  MBMU,PC
 SG_ BAT_Ucell_Max_48 : 32|16@1+ (1,0) [0|65535] "mV"  MBMU,PC
 SG_ BAT_Ucell_Min_48 : 48|16@1+ (1,0) [0|65535] "mV"  MBMU,PC

BO_ 2332295025 S2A_SUMDATA3__49: 8 SBMU
 SG_ CRC_S2A_S3_49 : 0|8@1+ (1,0) [0|255] ""  MBMU,PC
 SG_ BAT_Ucell_Max_CSC_49 : 8|6@1+ (1,0) [0|63] ""  MBMU,PC
 SG_ BAT_Ucell_Max_CELL_49 : 14|6@1+ (1,0) [0|63] ""  MBMU,PC
 SG_ BAT_Ucell_Min_CSC_49 : 20|6@1+ (1,0) [0|63] ""  MBMU,PC
 SG_ BAT_Ucell_Min_CELL_49 : 26|6@1+ (1,0) [0|63] ""  MBMU,PC
 SG_ BAT_Ucell_Max_49 : 32|16@1+ (1,0) [0|65535] "mV"  MBMU,PC
 SG_ BAT_Ucell_Min_49 : 48|16@1+ (1,0) [0|65535] "mV"  MBMU,PC

BO_ 2332295026 S2A_SUMDATA3__50: 8 SBMU
 SG_ CRC_S2A_S3_50 : 0|8@1+ (1,0) [0|255] ""  MBMU,PC
 SG_ BAT_Ucell_Max_CSC_50 : 8|6@1+ (1,0) [0|63] ""  MBMU,PC
 SG_ BAT_Ucell_Max_CELL_50 : 14|6@1+ (1,0) [0|63] ""  MBMU,PC
 SG_ BAT_Ucell_Min_CSC_50 : 20|6@1+ (1,0) [0|63] ""  MBMU,PC
 SG_ BAT_Ucell_Min_CELL_50 : 26|6@1+ (1,0) [0|63] ""  MBMU,PC
 SG_ BAT_Ucell_Max_50 : 32|16@1+ (1,0) [0|65535] "mV"  MBMU,PC
 SG_ BAT_Ucell_Min_50 : 48|16@1+ (1,0) [0|65535] "mV"  MBMU,PC

BO_ 2332295027 S2A_SUMDATA3__51: 8 SBMU
 SG_ CRC_S2A_S3_51 : 0|8@1+ (1,0) [0|255] ""  MBMU,PC
 SG_ BAT_Ucell_Max_CSC_51 : 8|6@1+ (1,0) [0|63] ""  MBMU,PC
 SG_ BAT_Ucell_Max_CELL_51 : 14|6@1+ (1,0) [0|63] ""  MBMU,PC
 SG_ BAT_Ucell_Min_CSC_51 : 20|6@1+ (1,0) [0|63] ""  MBMU,PC
 SG_ BAT_Ucell_Min_CELL_51 : 26|6@1+ (1,0) [0|63] ""  MBMU,PC
 SG_ BAT_Ucell_Max_51 : 32|16@1+ (1,0) [0|65535] "mV"  MBMU,PC
 SG_ BAT_Ucell_Min_51 : 48|16@1+ (1,0) [0|65535] "mV"  MBMU,PC

BO_ 2332295028 S2A_SUMDATA3__52: 8 SBMU
 SG_ CRC_S2A_S3_52 : 0|8@1+ (1,0) [0|255] ""  MBMU,PC
 SG_ BAT_Ucell_Max_CSC_52 : 8|6@1+ (1,0) [0|63] ""  MBMU,PC
 SG_ BAT_Ucell_Max_CELL_52 : 14|6@1+ (1,0) [0|63] ""  MBMU,PC
 SG_ BAT_Ucell_Min_CSC_52 : 20|6@1+ (1,0) [0|63] ""  MBMU,PC
 SG_ BAT_Ucell_Min_CELL_52 : 26|6@1+ (1,0) [0|63] ""  MBMU,PC
 SG_ BAT_Ucell_Max_52 : 32|16@1+ (1,0) [0|65535] "mV"  MBMU,PC
 SG_ BAT_Ucell_Min_52 : 48|16@1+ (1,0) [0|65535] "mV"  MBMU,PC

BO_ 2332295029 S2A_SUMDATA3__53: 8 SBMU
 SG_ CRC_S2A_S3_53 : 0|8@1+ (1,0) [0|255] ""  MBMU,PC
 SG_ BAT_Ucell_Max_CSC_53 : 8|6@1+ (1,0) [0|63] ""  MBMU,PC
 SG_ BAT_Ucell_Max_CELL_53 : 14|6@1+ (1,0) [0|63] ""  MBMU,PC
 SG_ BAT_Ucell_Min_CSC_53 : 20|6@1+ (1,0) [0|63] ""  MBMU,PC
 SG_ BAT_Ucell_Min_CELL_53 : 26|6@1+ (1,0) [0|63] ""  MBMU,PC
 SG_ BAT_Ucell_Max_53 : 32|16@1+ (1,0) [0|65535] "mV"  MBMU,PC
 SG_ BAT_Ucell_Min_53 : 48|16@1+ (1,0) [0|65535] "mV"  MBMU,PC

BO_ 2332295030 S2A_SUMDATA3__54: 8 SBMU
 SG_ CRC_S2A_S3_54 : 0|8@1+ (1,0) [0|255] ""  MBMU,PC
 SG_ BAT_Ucell_Max_CSC_54 : 8|6@1+ (1,0) [0|63] ""  MBMU,PC
 SG_ BAT_Ucell_Max_CELL_54 : 14|6@1+ (1,0) [0|63] ""  MBMU,PC
 SG_ BAT_Ucell_Min_CSC_54 : 20|6@1+ (1,0) [0|63] ""  MBMU,PC
 SG_ BAT_Ucell_Min_CELL_54 : 26|6@1+ (1,0) [0|63] ""  MBMU,PC
 SG_ BAT_Ucell_Max_54 : 32|16@1+ (1,0) [0|65535] "mV"  MBMU,PC
 SG_ BAT_Ucell_Min_54 : 48|16@1+ (1,0) [0|65535] "mV"  MBMU,PC

BO_ 2332295031 S2A_SUMDATA3__55: 8 SBMU
 SG_ CRC_S2A_S3_55 : 0|8@1+ (1,0) [0|255] ""  MBMU,PC
 SG_ BAT_Ucell_Max_CSC_55 : 8|6@1+ (1,0) [0|63] ""  MBMU,PC
 SG_ BAT_Ucell_Max_CELL_55 : 14|6@1+ (1,0) [0|63] ""  MBMU,PC
 SG_ BAT_Ucell_Min_CSC_55 : 20|6@1+ (1,0) [0|63] ""  MBMU,PC
 SG_ BAT_Ucell_Min_CELL_55 : 26|6@1+ (1,0) [0|63] ""  MBMU,PC
 SG_ BAT_Ucell_Max_55 : 32|16@1+ (1,0) [0|65535] "mV"  MBMU,PC
 SG_ BAT_Ucell_Min_55 : 48|16@1+ (1,0) [0|65535] "mV"  MBMU,PC

BO_ 2332295032 S2A_SUMDATA3__56: 8 SBMU
 SG_ CRC_S2A_S3_56 : 0|8@1+ (1,0) [0|255] ""  MBMU,PC
 SG_ BAT_Ucell_Max_CSC_56 : 8|6@1+ (1,0) [0|63] ""  MBMU,PC
 SG_ BAT_Ucell_Max_CELL_56 : 14|6@1+ (1,0) [0|63] ""  MBMU,PC
 SG_ BAT_Ucell_Min_CSC_56 : 20|6@1+ (1,0) [0|63] ""  MBMU,PC
 SG_ BAT_Ucell_Min_CELL_56 : 26|6@1+ (1,0) [0|63] ""  MBMU,PC
 SG_ BAT_Ucell_Max_56 : 32|16@1+ (1,0) [0|65535] "mV"  MBMU,PC
 SG_ BAT_Ucell_Min_56 : 48|16@1+ (1,0) [0|65535] "mV"  MBMU,PC

BO_ 2332295033 S2A_SUMDATA3__57: 8 SBMU
 SG_ CRC_S2A_S3_57 : 0|8@1+ (1,0) [0|255] ""  MBMU,PC
 SG_ BAT_Ucell_Max_CSC_57 : 8|6@1+ (1,0) [0|63] ""  MBMU,PC
 SG_ BAT_Ucell_Max_CELL_57 : 14|6@1+ (1,0) [0|63] ""  MBMU,PC
 SG_ BAT_Ucell_Min_CSC_57 : 20|6@1+ (1,0) [0|63] ""  MBMU,PC
 SG_ BAT_Ucell_Min_CELL_57 : 26|6@1+ (1,0) [0|63] ""  MBMU,PC
 SG_ BAT_Ucell_Max_57 : 32|16@1+ (1,0) [0|65535] "mV"  MBMU,PC
 SG_ BAT_Ucell_Min_57 : 48|16@1+ (1,0) [0|65535] "mV"  MBMU,PC

BO_ 2332295034 S2A_SUMDATA3__58: 8 SBMU
 SG_ CRC_S2A_S3_58 : 0|8@1+ (1,0) [0|255] ""  MBMU,PC
 SG_ BAT_Ucell_Max_CSC_58 : 8|6@1+ (1,0) [0|63] ""  MBMU,PC
 SG_ BAT_Ucell_Max_CELL_58 : 14|6@1+ (1,0) [0|63] ""  MBMU,PC
 SG_ BAT_Ucell_Min_CSC_58 : 20|6@1+ (1,0) [0|63] ""  MBMU,PC
 SG_ BAT_Ucell_Min_CELL_58 : 26|6@1+ (1,0) [0|63] ""  MBMU,PC
 SG_ BAT_Ucell_Max_58 : 32|16@1+ (1,0) [0|65535] "mV"  MBMU,PC
 SG_ BAT_Ucell_Min_58 : 48|16@1+ (1,0) [0|65535] "mV"  MBMU,PC

BO_ 2332295035 S2A_SUMDATA3__59: 8 SBMU
 SG_ CRC_S2A_S3_59 : 0|8@1+ (1,0) [0|255] ""  MBMU,PC
 SG_ BAT_Ucell_Max_CSC_59 : 8|6@1+ (1,0) [0|63] ""  MBMU,PC
 SG_ BAT_Ucell_Max_CELL_59 : 14|6@1+ (1,0) [0|63] ""  MBMU,PC
 SG_ BAT_Ucell_Min_CSC_59 : 20|6@1+ (1,0) [0|63] ""  MBMU,PC
 SG_ BAT_Ucell_Min_CELL_59 : 26|6@1+ (1,0) [0|63] ""  MBMU,PC
 SG_ BAT_Ucell_Max_59 : 32|16@1+ (1,0) [0|65535] "mV"  MBMU,PC
 SG_ BAT_Ucell_Min_59 : 48|16@1+ (1,0) [0|65535] "mV"  MBMU,PC

BO_ 2332295036 S2A_SUMDATA3__60: 8 SBMU
 SG_ CRC_S2A_S3_60 : 0|8@1+ (1,0) [0|255] ""  MBMU,PC
 SG_ BAT_Ucell_Max_CSC_60 : 8|6@1+ (1,0) [0|63] ""  MBMU,PC
 SG_ BAT_Ucell_Max_CELL_60 : 14|6@1+ (1,0) [0|63] ""  MBMU,PC
 SG_ BAT_Ucell_Min_CSC_60 : 20|6@1+ (1,0) [0|63] ""  MBMU,PC
 SG_ BAT_Ucell_Min_CELL_60 : 26|6@1+ (1,0) [0|63] ""  MBMU,PC
 SG_ BAT_Ucell_Max_60 : 32|16@1+ (1,0) [0|65535] "mV"  MBMU,PC
 SG_ BAT_Ucell_Min_60 : 48|16@1+ (1,0) [0|65535] "mV"  MBMU,PC

BO_ 2332295037 S2A_SUMDATA3__61: 8 SBMU
 SG_ CRC_S2A_S3_61 : 0|8@1+ (1,0) [0|255] ""  MBMU,PC
 SG_ BAT_Ucell_Max_CSC_61 : 8|6@1+ (1,0) [0|63] ""  MBMU,PC
 SG_ BAT_Ucell_Max_CELL_61 : 14|6@1+ (1,0) [0|63] ""  MBMU,PC
 SG_ BAT_Ucell_Min_CSC_61 : 20|6@1+ (1,0) [0|63] ""  MBMU,PC
 SG_ BAT_Ucell_Min_CELL_61 : 26|6@1+ (1,0) [0|63] ""  MBMU,PC
 SG_ BAT_Ucell_Max_61 : 32|16@1+ (1,0) [0|65535] "mV"  MBMU,PC
 SG_ BAT_Ucell_Min_61 : 48|16@1+ (1,0) [0|65535] "mV"  MBMU,PC

BO_ 2332295038 S2A_SUMDATA3__62: 8 SBMU
 SG_ CRC_S2A_S3_62 : 0|8@1+ (1,0) [0|255] ""  MBMU,PC
 SG_ BAT_Ucell_Max_CSC_62 : 8|6@1+ (1,0) [0|63] ""  MBMU,PC
 SG_ BAT_Ucell_Max_CELL_62 : 14|6@1+ (1,0) [0|63] ""  MBMU,PC
 SG_ BAT_Ucell_Min_CSC_62 : 20|6@1+ (1,0) [0|63] ""  MBMU,PC
 SG_ BAT_Ucell_Min_CELL_62 : 26|6@1+ (1,0) [0|63] ""  MBMU,PC
 SG_ BAT_Ucell_Max_62 : 32|16@1+ (1,0) [0|65535] "mV"  MBMU,PC
 SG_ BAT_Ucell_Min_62 : 48|16@1+ (1,0) [0|65535] "mV"  MBMU,PC

BO_ 2332295039 S2A_SUMDATA3__63: 8 SBMU
 SG_ CRC_S2A_S3_63 : 0|8@1+ (1,0) [0|255] ""  MBMU,PC
 SG_ BAT_Ucell_Max_CSC_63 : 8|6@1+ (1,0) [0|63] ""  MBMU,PC
 SG_ BAT_Ucell_Max_CELL_63 : 14|6@1+ (1,0) [0|63] ""  MBMU,PC
 SG_ BAT_Ucell_Min_CSC_63 : 20|6@1+ (1,0) [0|63] ""  MBMU,PC
 SG_ BAT_Ucell_Min_CELL_63 : 26|6@1+ (1,0) [0|63] ""  MBMU,PC
 SG_ BAT_Ucell_Max_63 : 32|16@1+ (1,0) [0|65535] "mV"  MBMU,PC
 SG_ BAT_Ucell_Min_63 : 48|16@1+ (1,0) [0|65535] "mV"  MBMU,PC

BO_ 2332360513 S2A_SUMDATA4__01: 8 SBMU
 SG_ CRC_S2A_S4_01 : 0|8@1+ (1,0) [0|255] ""  MBMU,PC
 SG_ BAT_Ucell_Avg_01 : 8|16@1+ (1,0) [0|65535] "mV"  MBMU,PC
 SG_ BAT_T_Max_01 : 24|8@1+ (1,-50) [-50|205] "℃"  MBMU,PC
 SG_ BAT_T_Min_01 : 32|8@1+ (1,-50) [-50|205] "℃"  MBMU,PC
 SG_ BAT_T_Avg_01 : 40|8@1+ (1,-50) [-50|205] "℃"  MBMU,PC
 SG_ BAT_T_Max_CSC_01 : 48|8@1+ (1,0) [0|255] ""  MBMU,PC
 SG_ BAT_T_Min_CSC_01 : 56|8@1+ (1,0) [0|255] ""  MBMU,PC

BO_ 2332360514 S2A_SUMDATA4__02: 8 SBMU
 SG_ CRC_S2A_S4_02 : 0|8@1+ (1,0) [0|255] ""  MBMU,PC
 SG_ BAT_Ucell_Avg_02 : 8|16@1+ (1,0) [0|65535] "mV"  MBMU,PC
 SG_ BAT_T_Max_02 : 24|8@1+ (1,-50) [-50|205] "℃"  MBMU,PC
 SG_ BAT_T_Min_02 : 32|8@1+ (1,-50) [-50|205] "℃"  MBMU,PC
 SG_ BAT_T_Avg_02 : 40|8@1+ (1,-50) [-50|205] "℃"  MBMU,PC
 SG_ BAT_T_Max_CSC_02 : 48|8@1+ (1,0) [0|255] ""  MBMU,PC
 SG_ BAT_T_Min_CSC_02 : 56|8@1+ (1,0) [0|255] ""  MBMU,PC

BO_ 2332360515 S2A_SUMDATA4__03: 8 SBMU
 SG_ CRC_S2A_S4_03 : 0|8@1+ (1,0) [0|255] ""  MBMU,PC
 SG_ BAT_Ucell_Avg_03 : 8|16@1+ (1,0) [0|65535] "mV"  MBMU,PC
 SG_ BAT_T_Max_03 : 24|8@1+ (1,-50) [-50|205] "℃"  MBMU,PC
 SG_ BAT_T_Min_03 : 32|8@1+ (1,-50) [-50|205] "℃"  MBMU,PC
 SG_ BAT_T_Avg_03 : 40|8@1+ (1,-50) [-50|205] "℃"  MBMU,PC
 SG_ BAT_T_Max_CSC_03 : 48|8@1+ (1,0) [0|255] ""  MBMU,PC
 SG_ BAT_T_Min_CSC_03 : 56|8@1+ (1,0) [0|255] ""  MBMU,PC

BO_ 2332360516 S2A_SUMDATA4__04: 8 SBMU
 SG_ CRC_S2A_S4_04 : 0|8@1+ (1,0) [0|255] ""  MBMU,PC
 SG_ BAT_Ucell_Avg_04 : 8|16@1+ (1,0) [0|65535] "mV"  MBMU,PC
 SG_ BAT_T_Max_04 : 24|8@1+ (1,-50) [-50|205] "℃"  MBMU,PC
 SG_ BAT_T_Min_04 : 32|8@1+ (1,-50) [-50|205] "℃"  MBMU,PC
 SG_ BAT_T_Avg_04 : 40|8@1+ (1,-50) [-50|205] "℃"  MBMU,PC
 SG_ BAT_T_Max_CSC_04 : 48|8@1+ (1,0) [0|255] ""  MBMU,PC
 SG_ BAT_T_Min_CSC_04 : 56|8@1+ (1,0) [0|255] ""  MBMU,PC

BO_ 2332360517 S2A_SUMDATA4__05: 8 SBMU
 SG_ CRC_S2A_S4_05 : 0|8@1+ (1,0) [0|255] ""  MBMU,PC
 SG_ BAT_Ucell_Avg_05 : 8|16@1+ (1,0) [0|65535] "mV"  MBMU,PC
 SG_ BAT_T_Max_05 : 24|8@1+ (1,-50) [-50|205] "℃"  MBMU,PC
 SG_ BAT_T_Min_05 : 32|8@1+ (1,-50) [-50|205] "℃"  MBMU,PC
 SG_ BAT_T_Avg_05 : 40|8@1+ (1,-50) [-50|205] "℃"  MBMU,PC
 SG_ BAT_T_Max_CSC_05 : 48|8@1+ (1,0) [0|255] ""  MBMU,PC
 SG_ BAT_T_Min_CSC_05 : 56|8@1+ (1,0) [0|255] ""  MBMU,PC

BO_ 2332360518 S2A_SUMDATA4__06: 8 SBMU
 SG_ CRC_S2A_S4_06 : 0|8@1+ (1,0) [0|255] ""  MBMU,PC
 SG_ BAT_Ucell_Avg_06 : 8|16@1+ (1,0) [0|65535] "mV"  MBMU,PC
 SG_ BAT_T_Max_06 : 24|8@1+ (1,-50) [-50|205] "℃"  MBMU,PC
 SG_ BAT_T_Min_06 : 32|8@1+ (1,-50) [-50|205] "℃"  MBMU,PC
 SG_ BAT_T_Avg_06 : 40|8@1+ (1,-50) [-50|205] "℃"  MBMU,PC
 SG_ BAT_T_Max_CSC_06 : 48|8@1+ (1,0) [0|255] ""  MBMU,PC
 SG_ BAT_T_Min_CSC_06 : 56|8@1+ (1,0) [0|255] ""  MBMU,PC

BO_ 2332360519 S2A_SUMDATA4__07: 8 SBMU
 SG_ CRC_S2A_S4_07 : 0|8@1+ (1,0) [0|255] ""  MBMU,PC
 SG_ BAT_Ucell_Avg_07 : 8|16@1+ (1,0) [0|65535] "mV"  MBMU,PC
 SG_ BAT_T_Max_07 : 24|8@1+ (1,-50) [-50|205] "℃"  MBMU,PC
 SG_ BAT_T_Min_07 : 32|8@1+ (1,-50) [-50|205] "℃"  MBMU,PC
 SG_ BAT_T_Avg_07 : 40|8@1+ (1,-50) [-50|205] "℃"  MBMU,PC
 SG_ BAT_T_Max_CSC_07 : 48|8@1+ (1,0) [0|255] ""  MBMU,PC
 SG_ BAT_T_Min_CSC_07 : 56|8@1+ (1,0) [0|255] ""  MBMU,PC

BO_ 2332360520 S2A_SUMDATA4__08: 8 SBMU
 SG_ CRC_S2A_S4_08 : 0|8@1+ (1,0) [0|255] ""  MBMU,PC
 SG_ BAT_Ucell_Avg_08 : 8|16@1+ (1,0) [0|65535] "mV"  MBMU,PC
 SG_ BAT_T_Max_08 : 24|8@1+ (1,-50) [-50|205] "℃"  MBMU,PC
 SG_ BAT_T_Min_08 : 32|8@1+ (1,-50) [-50|205] "℃"  MBMU,PC
 SG_ BAT_T_Avg_08 : 40|8@1+ (1,-50) [-50|205] "℃"  MBMU,PC
 SG_ BAT_T_Max_CSC_08 : 48|8@1+ (1,0) [0|255] ""  MBMU,PC
 SG_ BAT_T_Min_CSC_08 : 56|8@1+ (1,0) [0|255] ""  MBMU,PC

BO_ 2332360521 S2A_SUMDATA4__09: 8 SBMU
 SG_ CRC_S2A_S4_09 : 0|8@1+ (1,0) [0|255] ""  MBMU,PC
 SG_ BAT_Ucell_Avg_09 : 8|16@1+ (1,0) [0|65535] "mV"  MBMU,PC
 SG_ BAT_T_Max_09 : 24|8@1+ (1,-50) [-50|205] "℃"  MBMU,PC
 SG_ BAT_T_Min_09 : 32|8@1+ (1,-50) [-50|205] "℃"  MBMU,PC
 SG_ BAT_T_Avg_09 : 40|8@1+ (1,-50) [-50|205] "℃"  MBMU,PC
 SG_ BAT_T_Max_CSC_09 : 48|8@1+ (1,0) [0|255] ""  MBMU,PC
 SG_ BAT_T_Min_CSC_09 : 56|8@1+ (1,0) [0|255] ""  MBMU,PC

BO_ 2332360522 S2A_SUMDATA4__10: 8 SBMU
 SG_ CRC_S2A_S4_10 : 0|8@1+ (1,0) [0|255] ""  MBMU,PC
 SG_ BAT_Ucell_Avg_10 : 8|16@1+ (1,0) [0|65535] "mV"  MBMU,PC
 SG_ BAT_T_Max_10 : 24|8@1+ (1,-50) [-50|205] "℃"  MBMU,PC
 SG_ BAT_T_Min_10 : 32|8@1+ (1,-50) [-50|205] "℃"  MBMU,PC
 SG_ BAT_T_Avg_10 : 40|8@1+ (1,-50) [-50|205] "℃"  MBMU,PC
 SG_ BAT_T_Max_CSC_10 : 48|8@1+ (1,0) [0|255] ""  MBMU,PC
 SG_ BAT_T_Min_CSC_10 : 56|8@1+ (1,0) [0|255] ""  MBMU,PC

BO_ 2332360523 S2A_SUMDATA4__11: 8 SBMU
 SG_ CRC_S2A_S4_11 : 0|8@1+ (1,0) [0|255] ""  MBMU,PC
 SG_ BAT_Ucell_Avg_11 : 8|16@1+ (1,0) [0|65535] "mV"  MBMU,PC
 SG_ BAT_T_Max_11 : 24|8@1+ (1,-50) [-50|205] "℃"  MBMU,PC
 SG_ BAT_T_Min_11 : 32|8@1+ (1,-50) [-50|205] "℃"  MBMU,PC
 SG_ BAT_T_Avg_11 : 40|8@1+ (1,-50) [-50|205] "℃"  MBMU,PC
 SG_ BAT_T_Max_CSC_11 : 48|8@1+ (1,0) [0|255] ""  MBMU,PC
 SG_ BAT_T_Min_CSC_11 : 56|8@1+ (1,0) [0|255] ""  MBMU,PC

BO_ 2332360524 S2A_SUMDATA4__12: 8 SBMU
 SG_ CRC_S2A_S4_12 : 0|8@1+ (1,0) [0|255] ""  MBMU,PC
 SG_ BAT_Ucell_Avg_12 : 8|16@1+ (1,0) [0|65535] "mV"  MBMU,PC
 SG_ BAT_T_Max_12 : 24|8@1+ (1,-50) [-50|205] "℃"  MBMU,PC
 SG_ BAT_T_Min_12 : 32|8@1+ (1,-50) [-50|205] "℃"  MBMU,PC
 SG_ BAT_T_Avg_12 : 40|8@1+ (1,-50) [-50|205] "℃"  MBMU,PC
 SG_ BAT_T_Max_CSC_12 : 48|8@1+ (1,0) [0|255] ""  MBMU,PC
 SG_ BAT_T_Min_CSC_12 : 56|8@1+ (1,0) [0|255] ""  MBMU,PC

BO_ 2332360525 S2A_SUMDATA4__13: 8 SBMU
 SG_ CRC_S2A_S4_13 : 0|8@1+ (1,0) [0|255] ""  MBMU,PC
 SG_ BAT_Ucell_Avg_13 : 8|16@1+ (1,0) [0|65535] "mV"  MBMU,PC
 SG_ BAT_T_Max_13 : 24|8@1+ (1,-50) [-50|205] "℃"  MBMU,PC
 SG_ BAT_T_Min_13 : 32|8@1+ (1,-50) [-50|205] "℃"  MBMU,PC
 SG_ BAT_T_Avg_13 : 40|8@1+ (1,-50) [-50|205] "℃"  MBMU,PC
 SG_ BAT_T_Max_CSC_13 : 48|8@1+ (1,0) [0|255] ""  MBMU,PC
 SG_ BAT_T_Min_CSC_13 : 56|8@1+ (1,0) [0|255] ""  MBMU,PC

BO_ 2332360526 S2A_SUMDATA4__14: 8 SBMU
 SG_ CRC_S2A_S4_14 : 0|8@1+ (1,0) [0|255] ""  MBMU,PC
 SG_ BAT_Ucell_Avg_14 : 8|16@1+ (1,0) [0|65535] "mV"  MBMU,PC
 SG_ BAT_T_Max_14 : 24|8@1+ (1,-50) [-50|205] "℃"  MBMU,PC
 SG_ BAT_T_Min_14 : 32|8@1+ (1,-50) [-50|205] "℃"  MBMU,PC
 SG_ BAT_T_Avg_14 : 40|8@1+ (1,-50) [-50|205] "℃"  MBMU,PC
 SG_ BAT_T_Max_CSC_14 : 48|8@1+ (1,0) [0|255] ""  MBMU,PC
 SG_ BAT_T_Min_CSC_14 : 56|8@1+ (1,0) [0|255] ""  MBMU,PC

BO_ 2332360527 S2A_SUMDATA4__15: 8 SBMU
 SG_ CRC_S2A_S4_15 : 0|8@1+ (1,0) [0|255] ""  MBMU,PC
 SG_ BAT_Ucell_Avg_15 : 8|16@1+ (1,0) [0|65535] "mV"  MBMU,PC
 SG_ BAT_T_Max_15 : 24|8@1+ (1,-50) [-50|205] "℃"  MBMU,PC
 SG_ BAT_T_Min_15 : 32|8@1+ (1,-50) [-50|205] "℃"  MBMU,PC
 SG_ BAT_T_Avg_15 : 40|8@1+ (1,-50) [-50|205] "℃"  MBMU,PC
 SG_ BAT_T_Max_CSC_15 : 48|8@1+ (1,0) [0|255] ""  MBMU,PC
 SG_ BAT_T_Min_CSC_15 : 56|8@1+ (1,0) [0|255] ""  MBMU,PC

BO_ 2332360528 S2A_SUMDATA4__16: 8 SBMU
 SG_ CRC_S2A_S4_16 : 0|8@1+ (1,0) [0|255] ""  MBMU,PC
 SG_ BAT_Ucell_Avg_16 : 8|16@1+ (1,0) [0|65535] "mV"  MBMU,PC
 SG_ BAT_T_Max_16 : 24|8@1+ (1,-50) [-50|205] "℃"  MBMU,PC
 SG_ BAT_T_Min_16 : 32|8@1+ (1,-50) [-50|205] "℃"  MBMU,PC
 SG_ BAT_T_Avg_16 : 40|8@1+ (1,-50) [-50|205] "℃"  MBMU,PC
 SG_ BAT_T_Max_CSC_16 : 48|8@1+ (1,0) [0|255] ""  MBMU,PC
 SG_ BAT_T_Min_CSC_16 : 56|8@1+ (1,0) [0|255] ""  MBMU,PC

BO_ 2332360529 S2A_SUMDATA4__17: 8 SBMU
 SG_ CRC_S2A_S4_17 : 0|8@1+ (1,0) [0|255] ""  MBMU,PC
 SG_ BAT_Ucell_Avg_17 : 8|16@1+ (1,0) [0|65535] "mV"  MBMU,PC
 SG_ BAT_T_Max_17 : 24|8@1+ (1,-50) [-50|205] "℃"  MBMU,PC
 SG_ BAT_T_Min_17 : 32|8@1+ (1,-50) [-50|205] "℃"  MBMU,PC
 SG_ BAT_T_Avg_17 : 40|8@1+ (1,-50) [-50|205] "℃"  MBMU,PC
 SG_ BAT_T_Max_CSC_17 : 48|8@1+ (1,0) [0|255] ""  MBMU,PC
 SG_ BAT_T_Min_CSC_17 : 56|8@1+ (1,0) [0|255] ""  MBMU,PC

BO_ 2332360530 S2A_SUMDATA4__18: 8 SBMU
 SG_ CRC_S2A_S4_18 : 0|8@1+ (1,0) [0|255] ""  MBMU,PC
 SG_ BAT_Ucell_Avg_18 : 8|16@1+ (1,0) [0|65535] "mV"  MBMU,PC
 SG_ BAT_T_Max_18 : 24|8@1+ (1,-50) [-50|205] "℃"  MBMU,PC
 SG_ BAT_T_Min_18 : 32|8@1+ (1,-50) [-50|205] "℃"  MBMU,PC
 SG_ BAT_T_Avg_18 : 40|8@1+ (1,-50) [-50|205] "℃"  MBMU,PC
 SG_ BAT_T_Max_CSC_18 : 48|8@1+ (1,0) [0|255] ""  MBMU,PC
 SG_ BAT_T_Min_CSC_18 : 56|8@1+ (1,0) [0|255] ""  MBMU,PC

BO_ 2332360531 S2A_SUMDATA4__19: 8 SBMU
 SG_ CRC_S2A_S4_19 : 0|8@1+ (1,0) [0|255] ""  MBMU,PC
 SG_ BAT_Ucell_Avg_19 : 8|16@1+ (1,0) [0|65535] "mV"  MBMU,PC
 SG_ BAT_T_Max_19 : 24|8@1+ (1,-50) [-50|205] "℃"  MBMU,PC
 SG_ BAT_T_Min_19 : 32|8@1+ (1,-50) [-50|205] "℃"  MBMU,PC
 SG_ BAT_T_Avg_19 : 40|8@1+ (1,-50) [-50|205] "℃"  MBMU,PC
 SG_ BAT_T_Max_CSC_19 : 48|8@1+ (1,0) [0|255] ""  MBMU,PC
 SG_ BAT_T_Min_CSC_19 : 56|8@1+ (1,0) [0|255] ""  MBMU,PC

BO_ 2332360532 S2A_SUMDATA4__20: 8 SBMU
 SG_ CRC_S2A_S4_20 : 0|8@1+ (1,0) [0|255] ""  MBMU,PC
 SG_ BAT_Ucell_Avg_20 : 8|16@1+ (1,0) [0|65535] "mV"  MBMU,PC
 SG_ BAT_T_Max_20 : 24|8@1+ (1,-50) [-50|205] "℃"  MBMU,PC
 SG_ BAT_T_Min_20 : 32|8@1+ (1,-50) [-50|205] "℃"  MBMU,PC
 SG_ BAT_T_Avg_20 : 40|8@1+ (1,-50) [-50|205] "℃"  MBMU,PC
 SG_ BAT_T_Max_CSC_20 : 48|8@1+ (1,0) [0|255] ""  MBMU,PC
 SG_ BAT_T_Min_CSC_20 : 56|8@1+ (1,0) [0|255] ""  MBMU,PC

BO_ 2332360533 S2A_SUMDATA4__21: 8 SBMU
 SG_ CRC_S2A_S4_21 : 0|8@1+ (1,0) [0|255] ""  MBMU,PC
 SG_ BAT_Ucell_Avg_21 : 8|16@1+ (1,0) [0|65535] "mV"  MBMU,PC
 SG_ BAT_T_Max_21 : 24|8@1+ (1,-50) [-50|205] "℃"  MBMU,PC
 SG_ BAT_T_Min_21 : 32|8@1+ (1,-50) [-50|205] "℃"  MBMU,PC
 SG_ BAT_T_Avg_21 : 40|8@1+ (1,-50) [-50|205] "℃"  MBMU,PC
 SG_ BAT_T_Max_CSC_21 : 48|8@1+ (1,0) [0|255] ""  MBMU,PC
 SG_ BAT_T_Min_CSC_21 : 56|8@1+ (1,0) [0|255] ""  MBMU,PC

BO_ 2332360534 S2A_SUMDATA4__22: 8 SBMU
 SG_ CRC_S2A_S4_22 : 0|8@1+ (1,0) [0|255] ""  MBMU,PC
 SG_ BAT_Ucell_Avg_22 : 8|16@1+ (1,0) [0|65535] "mV"  MBMU,PC
 SG_ BAT_T_Max_22 : 24|8@1+ (1,-50) [-50|205] "℃"  MBMU,PC
 SG_ BAT_T_Min_22 : 32|8@1+ (1,-50) [-50|205] "℃"  MBMU,PC
 SG_ BAT_T_Avg_22 : 40|8@1+ (1,-50) [-50|205] "℃"  MBMU,PC
 SG_ BAT_T_Max_CSC_22 : 48|8@1+ (1,0) [0|255] ""  MBMU,PC
 SG_ BAT_T_Min_CSC_22 : 56|8@1+ (1,0) [0|255] ""  MBMU,PC

BO_ 2332360535 S2A_SUMDATA4__23: 8 SBMU
 SG_ CRC_S2A_S4_23 : 0|8@1+ (1,0) [0|255] ""  MBMU,PC
 SG_ BAT_Ucell_Avg_23 : 8|16@1+ (1,0) [0|65535] "mV"  MBMU,PC
 SG_ BAT_T_Max_23 : 24|8@1+ (1,-50) [-50|205] "℃"  MBMU,PC
 SG_ BAT_T_Min_23 : 32|8@1+ (1,-50) [-50|205] "℃"  MBMU,PC
 SG_ BAT_T_Avg_23 : 40|8@1+ (1,-50) [-50|205] "℃"  MBMU,PC
 SG_ BAT_T_Max_CSC_23 : 48|8@1+ (1,0) [0|255] ""  MBMU,PC
 SG_ BAT_T_Min_CSC_23 : 56|8@1+ (1,0) [0|255] ""  MBMU,PC

BO_ 2332360536 S2A_SUMDATA4__24: 8 SBMU
 SG_ CRC_S2A_S4_24 : 0|8@1+ (1,0) [0|255] ""  MBMU,PC
 SG_ BAT_Ucell_Avg_24 : 8|16@1+ (1,0) [0|65535] "mV"  MBMU,PC
 SG_ BAT_T_Max_24 : 24|8@1+ (1,-50) [-50|205] "℃"  MBMU,PC
 SG_ BAT_T_Min_24 : 32|8@1+ (1,-50) [-50|205] "℃"  MBMU,PC
 SG_ BAT_T_Avg_24 : 40|8@1+ (1,-50) [-50|205] "℃"  MBMU,PC
 SG_ BAT_T_Max_CSC_24 : 48|8@1+ (1,0) [0|255] ""  MBMU,PC
 SG_ BAT_T_Min_CSC_24 : 56|8@1+ (1,0) [0|255] ""  MBMU,PC

BO_ 2332360537 S2A_SUMDATA4__25: 8 SBMU
 SG_ CRC_S2A_S4_25 : 0|8@1+ (1,0) [0|255] ""  MBMU,PC
 SG_ BAT_Ucell_Avg_25 : 8|16@1+ (1,0) [0|65535] "mV"  MBMU,PC
 SG_ BAT_T_Max_25 : 24|8@1+ (1,-50) [-50|205] "℃"  MBMU,PC
 SG_ BAT_T_Min_25 : 32|8@1+ (1,-50) [-50|205] "℃"  MBMU,PC
 SG_ BAT_T_Avg_25 : 40|8@1+ (1,-50) [-50|205] "℃"  MBMU,PC
 SG_ BAT_T_Max_CSC_25 : 48|8@1+ (1,0) [0|255] ""  MBMU,PC
 SG_ BAT_T_Min_CSC_25 : 56|8@1+ (1,0) [0|255] ""  MBMU,PC

BO_ 2332360538 S2A_SUMDATA4__26: 8 SBMU
 SG_ CRC_S2A_S4_26 : 0|8@1+ (1,0) [0|255] ""  MBMU,PC
 SG_ BAT_Ucell_Avg_26 : 8|16@1+ (1,0) [0|65535] "mV"  MBMU,PC
 SG_ BAT_T_Max_26 : 24|8@1+ (1,-50) [-50|205] "℃"  MBMU,PC
 SG_ BAT_T_Min_26 : 32|8@1+ (1,-50) [-50|205] "℃"  MBMU,PC
 SG_ BAT_T_Avg_26 : 40|8@1+ (1,-50) [-50|205] "℃"  MBMU,PC
 SG_ BAT_T_Max_CSC_26 : 48|8@1+ (1,0) [0|255] ""  MBMU,PC
 SG_ BAT_T_Min_CSC_26 : 56|8@1+ (1,0) [0|255] ""  MBMU,PC

BO_ 2332360539 S2A_SUMDATA4__27: 8 SBMU
 SG_ CRC_S2A_S4_27 : 0|8@1+ (1,0) [0|255] ""  MBMU,PC
 SG_ BAT_Ucell_Avg_27 : 8|16@1+ (1,0) [0|65535] "mV"  MBMU,PC
 SG_ BAT_T_Max_27 : 24|8@1+ (1,-50) [-50|205] "℃"  MBMU,PC
 SG_ BAT_T_Min_27 : 32|8@1+ (1,-50) [-50|205] "℃"  MBMU,PC
 SG_ BAT_T_Avg_27 : 40|8@1+ (1,-50) [-50|205] "℃"  MBMU,PC
 SG_ BAT_T_Max_CSC_27 : 48|8@1+ (1,0) [0|255] ""  MBMU,PC
 SG_ BAT_T_Min_CSC_27 : 56|8@1+ (1,0) [0|255] ""  MBMU,PC

BO_ 2332360540 S2A_SUMDATA4__28: 8 SBMU
 SG_ CRC_S2A_S4_28 : 0|8@1+ (1,0) [0|255] ""  MBMU,PC
 SG_ BAT_Ucell_Avg_28 : 8|16@1+ (1,0) [0|65535] "mV"  MBMU,PC
 SG_ BAT_T_Max_28 : 24|8@1+ (1,-50) [-50|205] "℃"  MBMU,PC
 SG_ BAT_T_Min_28 : 32|8@1+ (1,-50) [-50|205] "℃"  MBMU,PC
 SG_ BAT_T_Avg_28 : 40|8@1+ (1,-50) [-50|205] "℃"  MBMU,PC
 SG_ BAT_T_Max_CSC_28 : 48|8@1+ (1,0) [0|255] ""  MBMU,PC
 SG_ BAT_T_Min_CSC_28 : 56|8@1+ (1,0) [0|255] ""  MBMU,PC

BO_ 2332360541 S2A_SUMDATA4__29: 8 SBMU
 SG_ CRC_S2A_S4_29 : 0|8@1+ (1,0) [0|255] ""  MBMU,PC
 SG_ BAT_Ucell_Avg_29 : 8|16@1+ (1,0) [0|65535] "mV"  MBMU,PC
 SG_ BAT_T_Max_29 : 24|8@1+ (1,-50) [-50|205] "℃"  MBMU,PC
 SG_ BAT_T_Min_29 : 32|8@1+ (1,-50) [-50|205] "℃"  MBMU,PC
 SG_ BAT_T_Avg_29 : 40|8@1+ (1,-50) [-50|205] "℃"  MBMU,PC
 SG_ BAT_T_Max_CSC_29 : 48|8@1+ (1,0) [0|255] ""  MBMU,PC
 SG_ BAT_T_Min_CSC_29 : 56|8@1+ (1,0) [0|255] ""  MBMU,PC

BO_ 2332360542 S2A_SUMDATA4__30: 8 SBMU
 SG_ CRC_S2A_S4_30 : 0|8@1+ (1,0) [0|255] ""  MBMU,PC
 SG_ BAT_Ucell_Avg_30 : 8|16@1+ (1,0) [0|65535] "mV"  MBMU,PC
 SG_ BAT_T_Max_30 : 24|8@1+ (1,-50) [-50|205] "℃"  MBMU,PC
 SG_ BAT_T_Min_30 : 32|8@1+ (1,-50) [-50|205] "℃"  MBMU,PC
 SG_ BAT_T_Avg_30 : 40|8@1+ (1,-50) [-50|205] "℃"  MBMU,PC
 SG_ BAT_T_Max_CSC_30 : 48|8@1+ (1,0) [0|255] ""  MBMU,PC
 SG_ BAT_T_Min_CSC_30 : 56|8@1+ (1,0) [0|255] ""  MBMU,PC

CM_ SG_ 2332229470 CRC_S2A_S2_30 "S2A概要数据2 的CRC";
CM_ SG_ 2332229470 ALIV_ST_SW_HVS_30 "生命信号，0~15循环";
CM_ SG_ 2332229470 ST_PreCharge_SW_HVS_30 "预充继电器驱动状态  备注：应用层的驱动指令信号";
CM_ SG_ 2332229470 ST_Main_POS_SW_HVS_30 "主正继电器驱动状态 备注：应用层的驱动指令信号";
CM_ SG_ 2332229470 ST_Main_NEG_SW_HVS_30 "主负继电器驱动状态 备注：应用层的驱动指令信号";
CM_ SG_ 2332229470 ST_System_30 "单柜是否允许上高压状态                                 未上高压前：0 为不允许上高压，1为允许上高压。上高压后：0为请求下高压，1为允许正常使用。";
CM_ SG_ 2332229470 ST_CALIBRATION_30 "单柜调试模式反馈                                   P2S调整报文发送（0x01 继电器指令，0x02 均衡指令，0x03 风机指令）信号的反馈状态，0是未接收相关的调试指令，1：接收到相关的调试指令";
CM_ SG_ 2332229470 ST_Insulation_30 "预留";
CM_ SG_ 2332229470 ST_PowerDown_30 "SBMU的供电输出低压电源状态                                                                           当前信号为低压相关的信号，发送的内部接口为：SeBMSM_LvPwrState 。含义为：SBMU低压电源运行状态反馈标志 ";
CM_ SG_ 2332229470 ST_pwr12V_30 "MCU反馈的12V电源pin应答状态";
CM_ SG_ 2332229470 ST_pwr5V_30 "预留";
CM_ SG_ 2332229470 ST_pwr24V_30 "通过MCU反馈的24V电源pin应答状态";
CM_ SG_ 2332229470 ST_pwrStatus_30 "单柜高压状态                                        当前为上高压完成信号：SbPRCC_HvPwrOnFinishFlg
 1,主正继电器的驱动指令为驱动闭合状态，且真实状态为闭合状态                                    2,主负继电器的驱动指令为驱动闭合状态，且真实状态为闭合状态                                     3, 预充继电器驱动指令为断开状态；                      同时满足条件1,2,3后保持1s 后该信号置为高压已上电
";
CM_ SG_ 2332229470 S2A_S2_FullChgFlgFromSBMU_30 "满充标志位";
CM_ SG_ 2332229470 ST_cscStandby_30 "CSC工作状态";
CM_ SG_ 2332229470 ST_OffReasonMsg_30 "主回路断开原因—每个bit代表一个原因，当前仅发送了前16个bit
 具体含义如下：
 Bit0: 高压无效Bit1:驱动短地Bit2:故障禁止上高压 forbid closeBit3:CSC编码中Bit4:概要数据中电压无效Bit5:概要数据温度无Bit6:预留调试模式（未使用）Bit7-Bit9: （未使用）Bit10: 未收到上高压指令Bit11: 故障强制断开继电器（force open）Bit12: 故障延迟断开继电器（normal Open）Bit13-Bit15: （未使用）";
CM_ SG_ 2332229471 CRC_S2A_S2_31 "S2A概要数据2 的CRC";
CM_ SG_ 2332229471 ALIV_ST_SW_HVS_31 "生命信号，0~15循环";
CM_ SG_ 2332229471 ST_PreCharge_SW_HVS_31 "预充继电器驱动状态  备注：应用层的驱动指令信号";
CM_ SG_ 2332229471 ST_Main_POS_SW_HVS_31 "主正继电器驱动状态 备注：应用层的驱动指令信号";
CM_ SG_ 2332229471 ST_Main_NEG_SW_HVS_31 "主负继电器驱动状态 备注：应用层的驱动指令信号";
CM_ SG_ 2332229471 ST_System_31 "单柜是否允许上高压状态                                 未上高压前：0 为不允许上高压，1为允许上高压。上高压后：0为请求下高压，1为允许正常使用。";
CM_ SG_ 2332229471 ST_CALIBRATION_31 "单柜调试模式反馈                                   P2S调整报文发送（0x01 继电器指令，0x02 均衡指令，0x03 风机指令）信号的反馈状态，0是未接收相关的调试指令，1：接收到相关的调试指令";
CM_ SG_ 2332229471 ST_Insulation_31 "预留";
CM_ SG_ 2332229471 ST_PowerDown_31 "SBMU的供电输出低压电源状态                                                                           当前信号为低压相关的信号，发送的内部接口为：SeBMSM_LvPwrState 。含义为：SBMU低压电源运行状态反馈标志 ";
CM_ SG_ 2332229471 ST_pwr12V_31 "MCU反馈的12V电源pin应答状态";
CM_ SG_ 2332229471 ST_pwr5V_31 "预留";
CM_ SG_ 2332229471 ST_pwr24V_31 "通过MCU反馈的24V电源pin应答状态";
CM_ SG_ 2332229471 ST_pwrStatus_31 "单柜高压状态                                        当前为上高压完成信号：SbPRCC_HvPwrOnFinishFlg
 1,主正继电器的驱动指令为驱动闭合状态，且真实状态为闭合状态                                    2,主负继电器的驱动指令为驱动闭合状态，且真实状态为闭合状态                                     3, 预充继电器驱动指令为断开状态；                      同时满足条件1,2,3后保持1s 后该信号置为高压已上电
";
CM_ SG_ 2332229471 S2A_S2_FullChgFlgFromSBMU_31 "满充标志位";
CM_ SG_ 2332229471 ST_cscStandby_31 "CSC工作状态";
CM_ SG_ 2332229471 ST_OffReasonMsg_31 "主回路断开原因—每个bit代表一个原因，当前仅发送了前16个bit
 具体含义如下：
 Bit0: 高压无效Bit1:驱动短地Bit2:故障禁止上高压 forbid closeBit3:CSC编码中Bit4:概要数据中电压无效Bit5:概要数据温度无Bit6:预留调试模式（未使用）Bit7-Bit9: （未使用）Bit10: 未收到上高压指令Bit11: 故障强制断开继电器（force open）Bit12: 故障延迟断开继电器（normal Open）Bit13-Bit15: （未使用）";
CM_ SG_ 2332229472 CRC_S2A_S2_32 "S2A概要数据2 的CRC";
CM_ SG_ 2332229472 ALIV_ST_SW_HVS_32 "生命信号，0~15循环";
CM_ SG_ 2332229472 ST_PreCharge_SW_HVS_32 "预充继电器驱动状态  备注：应用层的驱动指令信号";
CM_ SG_ 2332229472 ST_Main_POS_SW_HVS_32 "主正继电器驱动状态 备注：应用层的驱动指令信号";
CM_ SG_ 2332229472 ST_Main_NEG_SW_HVS_32 "主负继电器驱动状态 备注：应用层的驱动指令信号";
CM_ SG_ 2332229472 ST_System_32 "单柜是否允许上高压状态                                 未上高压前：0 为不允许上高压，1为允许上高压。上高压后：0为请求下高压，1为允许正常使用。";
CM_ SG_ 2332229472 ST_CALIBRATION_32 "单柜调试模式反馈                                   P2S调整报文发送（0x01 继电器指令，0x02 均衡指令，0x03 风机指令）信号的反馈状态，0是未接收相关的调试指令，1：接收到相关的调试指令";
CM_ SG_ 2332229472 ST_Insulation_32 "预留";
CM_ SG_ 2332229472 ST_PowerDown_32 "SBMU的供电输出低压电源状态                                                                           当前信号为低压相关的信号，发送的内部接口为：SeBMSM_LvPwrState 。含义为：SBMU低压电源运行状态反馈标志 ";
CM_ SG_ 2332229472 ST_pwr12V_32 "MCU反馈的12V电源pin应答状态";
CM_ SG_ 2332229472 ST_pwr5V_32 "预留";
CM_ SG_ 2332229472 ST_pwr24V_32 "通过MCU反馈的24V电源pin应答状态";
CM_ SG_ 2332229472 ST_pwrStatus_32 "单柜高压状态                                        当前为上高压完成信号：SbPRCC_HvPwrOnFinishFlg
 1,主正继电器的驱动指令为驱动闭合状态，且真实状态为闭合状态                                    2,主负继电器的驱动指令为驱动闭合状态，且真实状态为闭合状态                                     3, 预充继电器驱动指令为断开状态；                      同时满足条件1,2,3后保持1s 后该信号置为高压已上电
";
CM_ SG_ 2332229472 S2A_S2_FullChgFlgFromSBMU_32 "满充标志位";
CM_ SG_ 2332229472 ST_cscStandby_32 "CSC工作状态";
CM_ SG_ 2332229472 ST_OffReasonMsg_32 "主回路断开原因—每个bit代表一个原因，当前仅发送了前16个bit
 具体含义如下：
 Bit0: 高压无效Bit1:驱动短地Bit2:故障禁止上高压 forbid closeBit3:CSC编码中Bit4:概要数据中电压无效Bit5:概要数据温度无Bit6:预留调试模式（未使用）Bit7-Bit9: （未使用）Bit10: 未收到上高压指令Bit11: 故障强制断开继电器（force open）Bit12: 故障延迟断开继电器（normal Open）Bit13-Bit15: （未使用）";
CM_ SG_ 2332229473 CRC_S2A_S2_33 "S2A概要数据2 的CRC";
CM_ SG_ 2332229473 ALIV_ST_SW_HVS_33 "生命信号，0~15循环";
CM_ SG_ 2332229473 ST_PreCharge_SW_HVS_33 "预充继电器驱动状态  备注：应用层的驱动指令信号";
CM_ SG_ 2332229473 ST_Main_POS_SW_HVS_33 "主正继电器驱动状态 备注：应用层的驱动指令信号";
CM_ SG_ 2332229473 ST_Main_NEG_SW_HVS_33 "主负继电器驱动状态 备注：应用层的驱动指令信号";
CM_ SG_ 2332229473 ST_System_33 "单柜是否允许上高压状态                                 未上高压前：0 为不允许上高压，1为允许上高压。上高压后：0为请求下高压，1为允许正常使用。";
CM_ SG_ 2332229473 ST_CALIBRATION_33 "单柜调试模式反馈                                   P2S调整报文发送（0x01 继电器指令，0x02 均衡指令，0x03 风机指令）信号的反馈状态，0是未接收相关的调试指令，1：接收到相关的调试指令";
CM_ SG_ 2332229473 ST_Insulation_33 "预留";
CM_ SG_ 2332229473 ST_PowerDown_33 "SBMU的供电输出低压电源状态                                                                           当前信号为低压相关的信号，发送的内部接口为：SeBMSM_LvPwrState 。含义为：SBMU低压电源运行状态反馈标志 ";
CM_ SG_ 2332229473 ST_pwr12V_33 "MCU反馈的12V电源pin应答状态";
CM_ SG_ 2332229473 ST_pwr5V_33 "预留";
CM_ SG_ 2332229473 ST_pwr24V_33 "通过MCU反馈的24V电源pin应答状态";
CM_ SG_ 2332229473 ST_pwrStatus_33 "单柜高压状态                                        当前为上高压完成信号：SbPRCC_HvPwrOnFinishFlg
 1,主正继电器的驱动指令为驱动闭合状态，且真实状态为闭合状态                                    2,主负继电器的驱动指令为驱动闭合状态，且真实状态为闭合状态                                     3, 预充继电器驱动指令为断开状态；                      同时满足条件1,2,3后保持1s 后该信号置为高压已上电
";
CM_ SG_ 2332229473 S2A_S2_FullChgFlgFromSBMU_33 "满充标志位";
CM_ SG_ 2332229473 ST_cscStandby_33 "CSC工作状态";
CM_ SG_ 2332229473 ST_OffReasonMsg_33 "主回路断开原因—每个bit代表一个原因，当前仅发送了前16个bit
 具体含义如下：
 Bit0: 高压无效Bit1:驱动短地Bit2:故障禁止上高压 forbid closeBit3:CSC编码中Bit4:概要数据中电压无效Bit5:概要数据温度无Bit6:预留调试模式（未使用）Bit7-Bit9: （未使用）Bit10: 未收到上高压指令Bit11: 故障强制断开继电器（force open）Bit12: 故障延迟断开继电器（normal Open）Bit13-Bit15: （未使用）";
CM_ SG_ 2332229474 CRC_S2A_S2_34 "S2A概要数据2 的CRC";
CM_ SG_ 2332229474 ALIV_ST_SW_HVS_34 "生命信号，0~15循环";
CM_ SG_ 2332229474 ST_PreCharge_SW_HVS_34 "预充继电器驱动状态  备注：应用层的驱动指令信号";
CM_ SG_ 2332229474 ST_Main_POS_SW_HVS_34 "主正继电器驱动状态 备注：应用层的驱动指令信号";
CM_ SG_ 2332229474 ST_Main_NEG_SW_HVS_34 "主负继电器驱动状态 备注：应用层的驱动指令信号";
CM_ SG_ 2332229474 ST_System_34 "单柜是否允许上高压状态                                 未上高压前：0 为不允许上高压，1为允许上高压。上高压后：0为请求下高压，1为允许正常使用。";
CM_ SG_ 2332229474 ST_CALIBRATION_34 "单柜调试模式反馈                                   P2S调整报文发送（0x01 继电器指令，0x02 均衡指令，0x03 风机指令）信号的反馈状态，0是未接收相关的调试指令，1：接收到相关的调试指令";
CM_ SG_ 2332229474 ST_Insulation_34 "预留";
CM_ SG_ 2332229474 ST_PowerDown_34 "SBMU的供电输出低压电源状态                                                                           当前信号为低压相关的信号，发送的内部接口为：SeBMSM_LvPwrState 。含义为：SBMU低压电源运行状态反馈标志 ";
CM_ SG_ 2332229474 ST_pwr12V_34 "MCU反馈的12V电源pin应答状态";
CM_ SG_ 2332229474 ST_pwr5V_34 "预留";
CM_ SG_ 2332229474 ST_pwr24V_34 "通过MCU反馈的24V电源pin应答状态";
CM_ SG_ 2332229474 ST_pwrStatus_34 "单柜高压状态                                        当前为上高压完成信号：SbPRCC_HvPwrOnFinishFlg
 1,主正继电器的驱动指令为驱动闭合状态，且真实状态为闭合状态                                    2,主负继电器的驱动指令为驱动闭合状态，且真实状态为闭合状态                                     3, 预充继电器驱动指令为断开状态；                      同时满足条件1,2,3后保持1s 后该信号置为高压已上电
";
CM_ SG_ 2332229474 S2A_S2_FullChgFlgFromSBMU_34 "满充标志位";
CM_ SG_ 2332229474 ST_cscStandby_34 "CSC工作状态";
CM_ SG_ 2332229474 ST_OffReasonMsg_34 "主回路断开原因—每个bit代表一个原因，当前仅发送了前16个bit
 具体含义如下：
 Bit0: 高压无效Bit1:驱动短地Bit2:故障禁止上高压 forbid closeBit3:CSC编码中Bit4:概要数据中电压无效Bit5:概要数据温度无Bit6:预留调试模式（未使用）Bit7-Bit9: （未使用）Bit10: 未收到上高压指令Bit11: 故障强制断开继电器（force open）Bit12: 故障延迟断开继电器（normal Open）Bit13-Bit15: （未使用）";
CM_ SG_ 2332229475 CRC_S2A_S2_35 "S2A概要数据2 的CRC";
CM_ SG_ 2332229475 ALIV_ST_SW_HVS_35 "生命信号，0~15循环";
CM_ SG_ 2332229475 ST_PreCharge_SW_HVS_35 "预充继电器驱动状态  备注：应用层的驱动指令信号";
CM_ SG_ 2332229475 ST_Main_POS_SW_HVS_35 "主正继电器驱动状态 备注：应用层的驱动指令信号";
CM_ SG_ 2332229475 ST_Main_NEG_SW_HVS_35 "主负继电器驱动状态 备注：应用层的驱动指令信号";
CM_ SG_ 2332229475 ST_System_35 "单柜是否允许上高压状态                                 未上高压前：0 为不允许上高压，1为允许上高压。上高压后：0为请求下高压，1为允许正常使用。";
CM_ SG_ 2332229475 ST_CALIBRATION_35 "单柜调试模式反馈                                   P2S调整报文发送（0x01 继电器指令，0x02 均衡指令，0x03 风机指令）信号的反馈状态，0是未接收相关的调试指令，1：接收到相关的调试指令";
CM_ SG_ 2332229475 ST_Insulation_35 "预留";
CM_ SG_ 2332229475 ST_PowerDown_35 "SBMU的供电输出低压电源状态                                                                           当前信号为低压相关的信号，发送的内部接口为：SeBMSM_LvPwrState 。含义为：SBMU低压电源运行状态反馈标志 ";
CM_ SG_ 2332229475 ST_pwr12V_35 "MCU反馈的12V电源pin应答状态";
CM_ SG_ 2332229475 ST_pwr5V_35 "预留";
CM_ SG_ 2332229475 ST_pwr24V_35 "通过MCU反馈的24V电源pin应答状态";
CM_ SG_ 2332229475 ST_pwrStatus_35 "单柜高压状态                                        当前为上高压完成信号：SbPRCC_HvPwrOnFinishFlg
 1,主正继电器的驱动指令为驱动闭合状态，且真实状态为闭合状态                                    2,主负继电器的驱动指令为驱动闭合状态，且真实状态为闭合状态                                     3, 预充继电器驱动指令为断开状态；                      同时满足条件1,2,3后保持1s 后该信号置为高压已上电
";
CM_ SG_ 2332229475 S2A_S2_FullChgFlgFromSBMU_35 "满充标志位";
CM_ SG_ 2332229475 ST_cscStandby_35 "CSC工作状态";
CM_ SG_ 2332229475 ST_OffReasonMsg_35 "主回路断开原因—每个bit代表一个原因，当前仅发送了前16个bit
 具体含义如下：
 Bit0: 高压无效Bit1:驱动短地Bit2:故障禁止上高压 forbid closeBit3:CSC编码中Bit4:概要数据中电压无效Bit5:概要数据温度无Bit6:预留调试模式（未使用）Bit7-Bit9: （未使用）Bit10: 未收到上高压指令Bit11: 故障强制断开继电器（force open）Bit12: 故障延迟断开继电器（normal Open）Bit13-Bit15: （未使用）";
CM_ SG_ 2332229476 CRC_S2A_S2_36 "S2A概要数据2 的CRC";
CM_ SG_ 2332229476 ALIV_ST_SW_HVS_36 "生命信号，0~15循环";
CM_ SG_ 2332229476 ST_PreCharge_SW_HVS_36 "预充继电器驱动状态  备注：应用层的驱动指令信号";
CM_ SG_ 2332229476 ST_Main_POS_SW_HVS_36 "主正继电器驱动状态 备注：应用层的驱动指令信号";
CM_ SG_ 2332229476 ST_Main_NEG_SW_HVS_36 "主负继电器驱动状态 备注：应用层的驱动指令信号";
CM_ SG_ 2332229476 ST_System_36 "单柜是否允许上高压状态                                 未上高压前：0 为不允许上高压，1为允许上高压。上高压后：0为请求下高压，1为允许正常使用。";
CM_ SG_ 2332229476 ST_CALIBRATION_36 "单柜调试模式反馈                                   P2S调整报文发送（0x01 继电器指令，0x02 均衡指令，0x03 风机指令）信号的反馈状态，0是未接收相关的调试指令，1：接收到相关的调试指令";
CM_ SG_ 2332229476 ST_Insulation_36 "预留";
CM_ SG_ 2332229476 ST_PowerDown_36 "SBMU的供电输出低压电源状态                                                                           当前信号为低压相关的信号，发送的内部接口为：SeBMSM_LvPwrState 。含义为：SBMU低压电源运行状态反馈标志 ";
CM_ SG_ 2332229476 ST_pwr12V_36 "MCU反馈的12V电源pin应答状态";
CM_ SG_ 2332229476 ST_pwr5V_36 "预留";
CM_ SG_ 2332229476 ST_pwr24V_36 "通过MCU反馈的24V电源pin应答状态";
CM_ SG_ 2332229476 ST_pwrStatus_36 "单柜高压状态                                        当前为上高压完成信号：SbPRCC_HvPwrOnFinishFlg
 1,主正继电器的驱动指令为驱动闭合状态，且真实状态为闭合状态                                    2,主负继电器的驱动指令为驱动闭合状态，且真实状态为闭合状态                                     3, 预充继电器驱动指令为断开状态；                      同时满足条件1,2,3后保持1s 后该信号置为高压已上电
";
CM_ SG_ 2332229476 S2A_S2_FullChgFlgFromSBMU_36 "满充标志位";
CM_ SG_ 2332229476 ST_cscStandby_36 "CSC工作状态";
CM_ SG_ 2332229476 ST_OffReasonMsg_36 "主回路断开原因—每个bit代表一个原因，当前仅发送了前16个bit
 具体含义如下：
 Bit0: 高压无效Bit1:驱动短地Bit2:故障禁止上高压 forbid closeBit3:CSC编码中Bit4:概要数据中电压无效Bit5:概要数据温度无Bit6:预留调试模式（未使用）Bit7-Bit9: （未使用）Bit10: 未收到上高压指令Bit11: 故障强制断开继电器（force open）Bit12: 故障延迟断开继电器（normal Open）Bit13-Bit15: （未使用）";
CM_ SG_ 2332229477 CRC_S2A_S2_37 "S2A概要数据2 的CRC";
CM_ SG_ 2332229477 ALIV_ST_SW_HVS_37 "生命信号，0~15循环";
CM_ SG_ 2332229477 ST_PreCharge_SW_HVS_37 "预充继电器驱动状态  备注：应用层的驱动指令信号";
CM_ SG_ 2332229477 ST_Main_POS_SW_HVS_37 "主正继电器驱动状态 备注：应用层的驱动指令信号";
CM_ SG_ 2332229477 ST_Main_NEG_SW_HVS_37 "主负继电器驱动状态 备注：应用层的驱动指令信号";
CM_ SG_ 2332229477 ST_System_37 "单柜是否允许上高压状态                                 未上高压前：0 为不允许上高压，1为允许上高压。上高压后：0为请求下高压，1为允许正常使用。";
CM_ SG_ 2332229477 ST_CALIBRATION_37 "单柜调试模式反馈                                   P2S调整报文发送（0x01 继电器指令，0x02 均衡指令，0x03 风机指令）信号的反馈状态，0是未接收相关的调试指令，1：接收到相关的调试指令";
CM_ SG_ 2332229477 ST_Insulation_37 "预留";
CM_ SG_ 2332229477 ST_PowerDown_37 "SBMU的供电输出低压电源状态                                                                           当前信号为低压相关的信号，发送的内部接口为：SeBMSM_LvPwrState 。含义为：SBMU低压电源运行状态反馈标志 ";
CM_ SG_ 2332229477 ST_pwr12V_37 "MCU反馈的12V电源pin应答状态";
CM_ SG_ 2332229477 ST_pwr5V_37 "预留";
CM_ SG_ 2332229477 ST_pwr24V_37 "通过MCU反馈的24V电源pin应答状态";
CM_ SG_ 2332229477 ST_pwrStatus_37 "单柜高压状态                                        当前为上高压完成信号：SbPRCC_HvPwrOnFinishFlg
 1,主正继电器的驱动指令为驱动闭合状态，且真实状态为闭合状态                                    2,主负继电器的驱动指令为驱动闭合状态，且真实状态为闭合状态                                     3, 预充继电器驱动指令为断开状态；                      同时满足条件1,2,3后保持1s 后该信号置为高压已上电
";
CM_ SG_ 2332229477 S2A_S2_FullChgFlgFromSBMU_37 "满充标志位";
CM_ SG_ 2332229477 ST_cscStandby_37 "CSC工作状态";
CM_ SG_ 2332229477 ST_OffReasonMsg_37 "主回路断开原因—每个bit代表一个原因，当前仅发送了前16个bit
 具体含义如下：
 Bit0: 高压无效Bit1:驱动短地Bit2:故障禁止上高压 forbid closeBit3:CSC编码中Bit4:概要数据中电压无效Bit5:概要数据温度无Bit6:预留调试模式（未使用）Bit7-Bit9: （未使用）Bit10: 未收到上高压指令Bit11: 故障强制断开继电器（force open）Bit12: 故障延迟断开继电器（normal Open）Bit13-Bit15: （未使用）";
CM_ SG_ 2332229478 CRC_S2A_S2_38 "S2A概要数据2 的CRC";
CM_ SG_ 2332229478 ALIV_ST_SW_HVS_38 "生命信号，0~15循环";
CM_ SG_ 2332229478 ST_PreCharge_SW_HVS_38 "预充继电器驱动状态  备注：应用层的驱动指令信号";
CM_ SG_ 2332229478 ST_Main_POS_SW_HVS_38 "主正继电器驱动状态 备注：应用层的驱动指令信号";
CM_ SG_ 2332229478 ST_Main_NEG_SW_HVS_38 "主负继电器驱动状态 备注：应用层的驱动指令信号";
CM_ SG_ 2332229478 ST_System_38 "单柜是否允许上高压状态                                 未上高压前：0 为不允许上高压，1为允许上高压。上高压后：0为请求下高压，1为允许正常使用。";
CM_ SG_ 2332229478 ST_CALIBRATION_38 "单柜调试模式反馈                                   P2S调整报文发送（0x01 继电器指令，0x02 均衡指令，0x03 风机指令）信号的反馈状态，0是未接收相关的调试指令，1：接收到相关的调试指令";
CM_ SG_ 2332229478 ST_Insulation_38 "预留";
CM_ SG_ 2332229478 ST_PowerDown_38 "SBMU的供电输出低压电源状态                                                                           当前信号为低压相关的信号，发送的内部接口为：SeBMSM_LvPwrState 。含义为：SBMU低压电源运行状态反馈标志 ";
CM_ SG_ 2332229478 ST_pwr12V_38 "MCU反馈的12V电源pin应答状态";
CM_ SG_ 2332229478 ST_pwr5V_38 "预留";
CM_ SG_ 2332229478 ST_pwr24V_38 "通过MCU反馈的24V电源pin应答状态";
CM_ SG_ 2332229478 ST_pwrStatus_38 "单柜高压状态                                        当前为上高压完成信号：SbPRCC_HvPwrOnFinishFlg
 1,主正继电器的驱动指令为驱动闭合状态，且真实状态为闭合状态                                    2,主负继电器的驱动指令为驱动闭合状态，且真实状态为闭合状态                                     3, 预充继电器驱动指令为断开状态；                      同时满足条件1,2,3后保持1s 后该信号置为高压已上电
";
CM_ SG_ 2332229478 S2A_S2_FullChgFlgFromSBMU_38 "满充标志位";
CM_ SG_ 2332229478 ST_cscStandby_38 "CSC工作状态";
CM_ SG_ 2332229478 ST_OffReasonMsg_38 "主回路断开原因—每个bit代表一个原因，当前仅发送了前16个bit
 具体含义如下：
 Bit0: 高压无效Bit1:驱动短地Bit2:故障禁止上高压 forbid closeBit3:CSC编码中Bit4:概要数据中电压无效Bit5:概要数据温度无Bit6:预留调试模式（未使用）Bit7-Bit9: （未使用）Bit10: 未收到上高压指令Bit11: 故障强制断开继电器（force open）Bit12: 故障延迟断开继电器（normal Open）Bit13-Bit15: （未使用）";
CM_ SG_ 2332229479 CRC_S2A_S2_39 "S2A概要数据2 的CRC";
CM_ SG_ 2332229479 ALIV_ST_SW_HVS_39 "生命信号，0~15循环";
CM_ SG_ 2332229479 ST_PreCharge_SW_HVS_39 "预充继电器驱动状态  备注：应用层的驱动指令信号";
CM_ SG_ 2332229479 ST_Main_POS_SW_HVS_39 "主正继电器驱动状态 备注：应用层的驱动指令信号";
CM_ SG_ 2332229479 ST_Main_NEG_SW_HVS_39 "主负继电器驱动状态 备注：应用层的驱动指令信号";
CM_ SG_ 2332229479 ST_System_39 "单柜是否允许上高压状态                                 未上高压前：0 为不允许上高压，1为允许上高压。上高压后：0为请求下高压，1为允许正常使用。";
CM_ SG_ 2332229479 ST_CALIBRATION_39 "单柜调试模式反馈                                   P2S调整报文发送（0x01 继电器指令，0x02 均衡指令，0x03 风机指令）信号的反馈状态，0是未接收相关的调试指令，1：接收到相关的调试指令";
CM_ SG_ 2332229479 ST_Insulation_39 "预留";
CM_ SG_ 2332229479 ST_PowerDown_39 "SBMU的供电输出低压电源状态                                                                           当前信号为低压相关的信号，发送的内部接口为：SeBMSM_LvPwrState 。含义为：SBMU低压电源运行状态反馈标志 ";
CM_ SG_ 2332229479 ST_pwr12V_39 "MCU反馈的12V电源pin应答状态";
CM_ SG_ 2332229479 ST_pwr5V_39 "预留";
CM_ SG_ 2332229479 ST_pwr24V_39 "通过MCU反馈的24V电源pin应答状态";
CM_ SG_ 2332229479 ST_pwrStatus_39 "单柜高压状态                                        当前为上高压完成信号：SbPRCC_HvPwrOnFinishFlg
 1,主正继电器的驱动指令为驱动闭合状态，且真实状态为闭合状态                                    2,主负继电器的驱动指令为驱动闭合状态，且真实状态为闭合状态                                     3, 预充继电器驱动指令为断开状态；                      同时满足条件1,2,3后保持1s 后该信号置为高压已上电
";
CM_ SG_ 2332229479 S2A_S2_FullChgFlgFromSBMU_39 "满充标志位";
CM_ SG_ 2332229479 ST_cscStandby_39 "CSC工作状态";
CM_ SG_ 2332229479 ST_OffReasonMsg_39 "主回路断开原因—每个bit代表一个原因，当前仅发送了前16个bit
 具体含义如下：
 Bit0: 高压无效Bit1:驱动短地Bit2:故障禁止上高压 forbid closeBit3:CSC编码中Bit4:概要数据中电压无效Bit5:概要数据温度无Bit6:预留调试模式（未使用）Bit7-Bit9: （未使用）Bit10: 未收到上高压指令Bit11: 故障强制断开继电器（force open）Bit12: 故障延迟断开继电器（normal Open）Bit13-Bit15: （未使用）";
CM_ SG_ 2332229480 CRC_S2A_S2_40 "S2A概要数据2 的CRC";
CM_ SG_ 2332229480 ALIV_ST_SW_HVS_40 "生命信号，0~15循环";
CM_ SG_ 2332229480 ST_PreCharge_SW_HVS_40 "预充继电器驱动状态  备注：应用层的驱动指令信号";
CM_ SG_ 2332229480 ST_Main_POS_SW_HVS_40 "主正继电器驱动状态 备注：应用层的驱动指令信号";
CM_ SG_ 2332229480 ST_Main_NEG_SW_HVS_40 "主负继电器驱动状态 备注：应用层的驱动指令信号";
CM_ SG_ 2332229480 ST_System_40 "单柜是否允许上高压状态                                 未上高压前：0 为不允许上高压，1为允许上高压。上高压后：0为请求下高压，1为允许正常使用。";
CM_ SG_ 2332229480 ST_CALIBRATION_40 "单柜调试模式反馈                                   P2S调整报文发送（0x01 继电器指令，0x02 均衡指令，0x03 风机指令）信号的反馈状态，0是未接收相关的调试指令，1：接收到相关的调试指令";
CM_ SG_ 2332229480 ST_Insulation_40 "预留";
CM_ SG_ 2332229480 ST_PowerDown_40 "SBMU的供电输出低压电源状态                                                                           当前信号为低压相关的信号，发送的内部接口为：SeBMSM_LvPwrState 。含义为：SBMU低压电源运行状态反馈标志 ";
CM_ SG_ 2332229480 ST_pwr12V_40 "MCU反馈的12V电源pin应答状态";
CM_ SG_ 2332229480 ST_pwr5V_40 "预留";
CM_ SG_ 2332229480 ST_pwr24V_40 "通过MCU反馈的24V电源pin应答状态";
CM_ SG_ 2332229480 ST_pwrStatus_40 "单柜高压状态                                        当前为上高压完成信号：SbPRCC_HvPwrOnFinishFlg
 1,主正继电器的驱动指令为驱动闭合状态，且真实状态为闭合状态                                    2,主负继电器的驱动指令为驱动闭合状态，且真实状态为闭合状态                                     3, 预充继电器驱动指令为断开状态；                      同时满足条件1,2,3后保持1s 后该信号置为高压已上电
";
CM_ SG_ 2332229480 S2A_S2_FullChgFlgFromSBMU_40 "满充标志位";
CM_ SG_ 2332229480 ST_cscStandby_40 "CSC工作状态";
CM_ SG_ 2332229480 ST_OffReasonMsg_40 "主回路断开原因—每个bit代表一个原因，当前仅发送了前16个bit
 具体含义如下：
 Bit0: 高压无效Bit1:驱动短地Bit2:故障禁止上高压 forbid closeBit3:CSC编码中Bit4:概要数据中电压无效Bit5:概要数据温度无Bit6:预留调试模式（未使用）Bit7-Bit9: （未使用）Bit10: 未收到上高压指令Bit11: 故障强制断开继电器（force open）Bit12: 故障延迟断开继电器（normal Open）Bit13-Bit15: （未使用）";
CM_ SG_ 2332229481 CRC_S2A_S2_41 "S2A概要数据2 的CRC";
CM_ SG_ 2332229481 ALIV_ST_SW_HVS_41 "生命信号，0~15循环";
CM_ SG_ 2332229481 ST_PreCharge_SW_HVS_41 "预充继电器驱动状态  备注：应用层的驱动指令信号";
CM_ SG_ 2332229481 ST_Main_POS_SW_HVS_41 "主正继电器驱动状态 备注：应用层的驱动指令信号";
CM_ SG_ 2332229481 ST_Main_NEG_SW_HVS_41 "主负继电器驱动状态 备注：应用层的驱动指令信号";
CM_ SG_ 2332229481 ST_System_41 "单柜是否允许上高压状态                                 未上高压前：0 为不允许上高压，1为允许上高压。上高压后：0为请求下高压，1为允许正常使用。";
CM_ SG_ 2332229481 ST_CALIBRATION_41 "单柜调试模式反馈                                   P2S调整报文发送（0x01 继电器指令，0x02 均衡指令，0x03 风机指令）信号的反馈状态，0是未接收相关的调试指令，1：接收到相关的调试指令";
CM_ SG_ 2332229481 ST_Insulation_41 "预留";
CM_ SG_ 2332229481 ST_PowerDown_41 "SBMU的供电输出低压电源状态                                                                           当前信号为低压相关的信号，发送的内部接口为：SeBMSM_LvPwrState 。含义为：SBMU低压电源运行状态反馈标志 ";
CM_ SG_ 2332229481 ST_pwr12V_41 "MCU反馈的12V电源pin应答状态";
CM_ SG_ 2332229481 ST_pwr5V_41 "预留";
CM_ SG_ 2332229481 ST_pwr24V_41 "通过MCU反馈的24V电源pin应答状态";
CM_ SG_ 2332229481 ST_pwrStatus_41 "单柜高压状态                                        当前为上高压完成信号：SbPRCC_HvPwrOnFinishFlg
 1,主正继电器的驱动指令为驱动闭合状态，且真实状态为闭合状态                                    2,主负继电器的驱动指令为驱动闭合状态，且真实状态为闭合状态                                     3, 预充继电器驱动指令为断开状态；                      同时满足条件1,2,3后保持1s 后该信号置为高压已上电
";
CM_ SG_ 2332229481 S2A_S2_FullChgFlgFromSBMU_41 "满充标志位";
CM_ SG_ 2332229481 ST_cscStandby_41 "CSC工作状态";
CM_ SG_ 2332229481 ST_OffReasonMsg_41 "主回路断开原因—每个bit代表一个原因，当前仅发送了前16个bit
 具体含义如下：
 Bit0: 高压无效Bit1:驱动短地Bit2:故障禁止上高压 forbid closeBit3:CSC编码中Bit4:概要数据中电压无效Bit5:概要数据温度无Bit6:预留调试模式（未使用）Bit7-Bit9: （未使用）Bit10: 未收到上高压指令Bit11: 故障强制断开继电器（force open）Bit12: 故障延迟断开继电器（normal Open）Bit13-Bit15: （未使用）";
CM_ SG_ 2332229482 CRC_S2A_S2_42 "S2A概要数据2 的CRC";
CM_ SG_ 2332229482 ALIV_ST_SW_HVS_42 "生命信号，0~15循环";
CM_ SG_ 2332229482 ST_PreCharge_SW_HVS_42 "预充继电器驱动状态  备注：应用层的驱动指令信号";
CM_ SG_ 2332229482 ST_Main_POS_SW_HVS_42 "主正继电器驱动状态 备注：应用层的驱动指令信号";
CM_ SG_ 2332229482 ST_Main_NEG_SW_HVS_42 "主负继电器驱动状态 备注：应用层的驱动指令信号";
CM_ SG_ 2332229482 ST_System_42 "单柜是否允许上高压状态                                 未上高压前：0 为不允许上高压，1为允许上高压。上高压后：0为请求下高压，1为允许正常使用。";
CM_ SG_ 2332229482 ST_CALIBRATION_42 "单柜调试模式反馈                                   P2S调整报文发送（0x01 继电器指令，0x02 均衡指令，0x03 风机指令）信号的反馈状态，0是未接收相关的调试指令，1：接收到相关的调试指令";
CM_ SG_ 2332229482 ST_Insulation_42 "预留";
CM_ SG_ 2332229482 ST_PowerDown_42 "SBMU的供电输出低压电源状态                                                                           当前信号为低压相关的信号，发送的内部接口为：SeBMSM_LvPwrState 。含义为：SBMU低压电源运行状态反馈标志 ";
CM_ SG_ 2332229482 ST_pwr12V_42 "MCU反馈的12V电源pin应答状态";
CM_ SG_ 2332229482 ST_pwr5V_42 "预留";
CM_ SG_ 2332229482 ST_pwr24V_42 "通过MCU反馈的24V电源pin应答状态";
CM_ SG_ 2332229482 ST_pwrStatus_42 "单柜高压状态                                        当前为上高压完成信号：SbPRCC_HvPwrOnFinishFlg
 1,主正继电器的驱动指令为驱动闭合状态，且真实状态为闭合状态                                    2,主负继电器的驱动指令为驱动闭合状态，且真实状态为闭合状态                                     3, 预充继电器驱动指令为断开状态；                      同时满足条件1,2,3后保持1s 后该信号置为高压已上电
";
CM_ SG_ 2332229482 S2A_S2_FullChgFlgFromSBMU_42 "满充标志位";
CM_ SG_ 2332229482 ST_cscStandby_42 "CSC工作状态";
CM_ SG_ 2332229482 ST_OffReasonMsg_42 "主回路断开原因—每个bit代表一个原因，当前仅发送了前16个bit
 具体含义如下：
 Bit0: 高压无效Bit1:驱动短地Bit2:故障禁止上高压 forbid closeBit3:CSC编码中Bit4:概要数据中电压无效Bit5:概要数据温度无Bit6:预留调试模式（未使用）Bit7-Bit9: （未使用）Bit10: 未收到上高压指令Bit11: 故障强制断开继电器（force open）Bit12: 故障延迟断开继电器（normal Open）Bit13-Bit15: （未使用）";
CM_ SG_ 2332229483 CRC_S2A_S2_43 "S2A概要数据2 的CRC";
CM_ SG_ 2332229483 ALIV_ST_SW_HVS_43 "生命信号，0~15循环";
CM_ SG_ 2332229483 ST_PreCharge_SW_HVS_43 "预充继电器驱动状态  备注：应用层的驱动指令信号";
CM_ SG_ 2332229483 ST_Main_POS_SW_HVS_43 "主正继电器驱动状态 备注：应用层的驱动指令信号";
CM_ SG_ 2332229483 ST_Main_NEG_SW_HVS_43 "主负继电器驱动状态 备注：应用层的驱动指令信号";
CM_ SG_ 2332229483 ST_System_43 "单柜是否允许上高压状态                                 未上高压前：0 为不允许上高压，1为允许上高压。上高压后：0为请求下高压，1为允许正常使用。";
CM_ SG_ 2332229483 ST_CALIBRATION_43 "单柜调试模式反馈                                   P2S调整报文发送（0x01 继电器指令，0x02 均衡指令，0x03 风机指令）信号的反馈状态，0是未接收相关的调试指令，1：接收到相关的调试指令";
CM_ SG_ 2332229483 ST_Insulation_43 "预留";
CM_ SG_ 2332229483 ST_PowerDown_43 "SBMU的供电输出低压电源状态                                                                           当前信号为低压相关的信号，发送的内部接口为：SeBMSM_LvPwrState 。含义为：SBMU低压电源运行状态反馈标志 ";
CM_ SG_ 2332229483 ST_pwr12V_43 "MCU反馈的12V电源pin应答状态";
CM_ SG_ 2332229483 ST_pwr5V_43 "预留";
CM_ SG_ 2332229483 ST_pwr24V_43 "通过MCU反馈的24V电源pin应答状态";
CM_ SG_ 2332229483 ST_pwrStatus_43 "单柜高压状态                                        当前为上高压完成信号：SbPRCC_HvPwrOnFinishFlg
 1,主正继电器的驱动指令为驱动闭合状态，且真实状态为闭合状态                                    2,主负继电器的驱动指令为驱动闭合状态，且真实状态为闭合状态                                     3, 预充继电器驱动指令为断开状态；                      同时满足条件1,2,3后保持1s 后该信号置为高压已上电
";
CM_ SG_ 2332229483 S2A_S2_FullChgFlgFromSBMU_43 "满充标志位";
CM_ SG_ 2332229483 ST_cscStandby_43 "CSC工作状态";
CM_ SG_ 2332229483 ST_OffReasonMsg_43 "主回路断开原因—每个bit代表一个原因，当前仅发送了前16个bit
 具体含义如下：
 Bit0: 高压无效Bit1:驱动短地Bit2:故障禁止上高压 forbid closeBit3:CSC编码中Bit4:概要数据中电压无效Bit5:概要数据温度无Bit6:预留调试模式（未使用）Bit7-Bit9: （未使用）Bit10: 未收到上高压指令Bit11: 故障强制断开继电器（force open）Bit12: 故障延迟断开继电器（normal Open）Bit13-Bit15: （未使用）";
CM_ SG_ 2332229484 CRC_S2A_S2_44 "S2A概要数据2 的CRC";
CM_ SG_ 2332229484 ALIV_ST_SW_HVS_44 "生命信号，0~15循环";
CM_ SG_ 2332229484 ST_PreCharge_SW_HVS_44 "预充继电器驱动状态  备注：应用层的驱动指令信号";
CM_ SG_ 2332229484 ST_Main_POS_SW_HVS_44 "主正继电器驱动状态 备注：应用层的驱动指令信号";
CM_ SG_ 2332229484 ST_Main_NEG_SW_HVS_44 "主负继电器驱动状态 备注：应用层的驱动指令信号";
CM_ SG_ 2332229484 ST_System_44 "单柜是否允许上高压状态                                 未上高压前：0 为不允许上高压，1为允许上高压。上高压后：0为请求下高压，1为允许正常使用。";
CM_ SG_ 2332229484 ST_CALIBRATION_44 "单柜调试模式反馈                                   P2S调整报文发送（0x01 继电器指令，0x02 均衡指令，0x03 风机指令）信号的反馈状态，0是未接收相关的调试指令，1：接收到相关的调试指令";
CM_ SG_ 2332229484 ST_Insulation_44 "预留";
CM_ SG_ 2332229484 ST_PowerDown_44 "SBMU的供电输出低压电源状态                                                                           当前信号为低压相关的信号，发送的内部接口为：SeBMSM_LvPwrState 。含义为：SBMU低压电源运行状态反馈标志 ";
CM_ SG_ 2332229484 ST_pwr12V_44 "MCU反馈的12V电源pin应答状态";
CM_ SG_ 2332229484 ST_pwr5V_44 "预留";
CM_ SG_ 2332229484 ST_pwr24V_44 "通过MCU反馈的24V电源pin应答状态";
CM_ SG_ 2332229484 ST_pwrStatus_44 "单柜高压状态                                        当前为上高压完成信号：SbPRCC_HvPwrOnFinishFlg
 1,主正继电器的驱动指令为驱动闭合状态，且真实状态为闭合状态                                    2,主负继电器的驱动指令为驱动闭合状态，且真实状态为闭合状态                                     3, 预充继电器驱动指令为断开状态；                      同时满足条件1,2,3后保持1s 后该信号置为高压已上电
";
CM_ SG_ 2332229484 S2A_S2_FullChgFlgFromSBMU_44 "满充标志位";
CM_ SG_ 2332229484 ST_cscStandby_44 "CSC工作状态";
CM_ SG_ 2332229484 ST_OffReasonMsg_44 "主回路断开原因—每个bit代表一个原因，当前仅发送了前16个bit
 具体含义如下：
 Bit0: 高压无效Bit1:驱动短地Bit2:故障禁止上高压 forbid closeBit3:CSC编码中Bit4:概要数据中电压无效Bit5:概要数据温度无Bit6:预留调试模式（未使用）Bit7-Bit9: （未使用）Bit10: 未收到上高压指令Bit11: 故障强制断开继电器（force open）Bit12: 故障延迟断开继电器（normal Open）Bit13-Bit15: （未使用）";
CM_ SG_ 2332229485 CRC_S2A_S2_45 "S2A概要数据2 的CRC";
CM_ SG_ 2332229485 ALIV_ST_SW_HVS_45 "生命信号，0~15循环";
CM_ SG_ 2332229485 ST_PreCharge_SW_HVS_45 "预充继电器驱动状态  备注：应用层的驱动指令信号";
CM_ SG_ 2332229485 ST_Main_POS_SW_HVS_45 "主正继电器驱动状态 备注：应用层的驱动指令信号";
CM_ SG_ 2332229485 ST_Main_NEG_SW_HVS_45 "主负继电器驱动状态 备注：应用层的驱动指令信号";
CM_ SG_ 2332229485 ST_System_45 "单柜是否允许上高压状态                                 未上高压前：0 为不允许上高压，1为允许上高压。上高压后：0为请求下高压，1为允许正常使用。";
CM_ SG_ 2332229485 ST_CALIBRATION_45 "单柜调试模式反馈                                   P2S调整报文发送（0x01 继电器指令，0x02 均衡指令，0x03 风机指令）信号的反馈状态，0是未接收相关的调试指令，1：接收到相关的调试指令";
CM_ SG_ 2332229485 ST_Insulation_45 "预留";
CM_ SG_ 2332229485 ST_PowerDown_45 "SBMU的供电输出低压电源状态                                                                           当前信号为低压相关的信号，发送的内部接口为：SeBMSM_LvPwrState 。含义为：SBMU低压电源运行状态反馈标志 ";
CM_ SG_ 2332229485 ST_pwr12V_45 "MCU反馈的12V电源pin应答状态";
CM_ SG_ 2332229485 ST_pwr5V_45 "预留";
CM_ SG_ 2332229485 ST_pwr24V_45 "通过MCU反馈的24V电源pin应答状态";
CM_ SG_ 2332229485 ST_pwrStatus_45 "单柜高压状态                                        当前为上高压完成信号：SbPRCC_HvPwrOnFinishFlg
 1,主正继电器的驱动指令为驱动闭合状态，且真实状态为闭合状态                                    2,主负继电器的驱动指令为驱动闭合状态，且真实状态为闭合状态                                     3, 预充继电器驱动指令为断开状态；                      同时满足条件1,2,3后保持1s 后该信号置为高压已上电
";
CM_ SG_ 2332229485 S2A_S2_FullChgFlgFromSBMU_45 "满充标志位";
CM_ SG_ 2332229485 ST_cscStandby_45 "CSC工作状态";
CM_ SG_ 2332229485 ST_OffReasonMsg_45 "主回路断开原因—每个bit代表一个原因，当前仅发送了前16个bit
 具体含义如下：
 Bit0: 高压无效Bit1:驱动短地Bit2:故障禁止上高压 forbid closeBit3:CSC编码中Bit4:概要数据中电压无效Bit5:概要数据温度无Bit6:预留调试模式（未使用）Bit7-Bit9: （未使用）Bit10: 未收到上高压指令Bit11: 故障强制断开继电器（force open）Bit12: 故障延迟断开继电器（normal Open）Bit13-Bit15: （未使用）";
CM_ SG_ 2332229486 CRC_S2A_S2_46 "S2A概要数据2 的CRC";
CM_ SG_ 2332229486 ALIV_ST_SW_HVS_46 "生命信号，0~15循环";
CM_ SG_ 2332229486 ST_PreCharge_SW_HVS_46 "预充继电器驱动状态  备注：应用层的驱动指令信号";
CM_ SG_ 2332229486 ST_Main_POS_SW_HVS_46 "主正继电器驱动状态 备注：应用层的驱动指令信号";
CM_ SG_ 2332229486 ST_Main_NEG_SW_HVS_46 "主负继电器驱动状态 备注：应用层的驱动指令信号";
CM_ SG_ 2332229486 ST_System_46 "单柜是否允许上高压状态                                 未上高压前：0 为不允许上高压，1为允许上高压。上高压后：0为请求下高压，1为允许正常使用。";
CM_ SG_ 2332229486 ST_CALIBRATION_46 "单柜调试模式反馈                                   P2S调整报文发送（0x01 继电器指令，0x02 均衡指令，0x03 风机指令）信号的反馈状态，0是未接收相关的调试指令，1：接收到相关的调试指令";
CM_ SG_ 2332229486 ST_Insulation_46 "预留";
CM_ SG_ 2332229486 ST_PowerDown_46 "SBMU的供电输出低压电源状态                                                                           当前信号为低压相关的信号，发送的内部接口为：SeBMSM_LvPwrState 。含义为：SBMU低压电源运行状态反馈标志 ";
CM_ SG_ 2332229486 ST_pwr12V_46 "MCU反馈的12V电源pin应答状态";
CM_ SG_ 2332229486 ST_pwr5V_46 "预留";
CM_ SG_ 2332229486 ST_pwr24V_46 "通过MCU反馈的24V电源pin应答状态";
CM_ SG_ 2332229486 ST_pwrStatus_46 "单柜高压状态                                        当前为上高压完成信号：SbPRCC_HvPwrOnFinishFlg
 1,主正继电器的驱动指令为驱动闭合状态，且真实状态为闭合状态                                    2,主负继电器的驱动指令为驱动闭合状态，且真实状态为闭合状态                                     3, 预充继电器驱动指令为断开状态；                      同时满足条件1,2,3后保持1s 后该信号置为高压已上电
";
CM_ SG_ 2332229486 S2A_S2_FullChgFlgFromSBMU_46 "满充标志位";
CM_ SG_ 2332229486 ST_cscStandby_46 "CSC工作状态";
CM_ SG_ 2332229486 ST_OffReasonMsg_46 "主回路断开原因—每个bit代表一个原因，当前仅发送了前16个bit
 具体含义如下：
 Bit0: 高压无效Bit1:驱动短地Bit2:故障禁止上高压 forbid closeBit3:CSC编码中Bit4:概要数据中电压无效Bit5:概要数据温度无Bit6:预留调试模式（未使用）Bit7-Bit9: （未使用）Bit10: 未收到上高压指令Bit11: 故障强制断开继电器（force open）Bit12: 故障延迟断开继电器（normal Open）Bit13-Bit15: （未使用）";
CM_ SG_ 2332229487 CRC_S2A_S2_47 "S2A概要数据2 的CRC";
CM_ SG_ 2332229487 ALIV_ST_SW_HVS_47 "生命信号，0~15循环";
CM_ SG_ 2332229487 ST_PreCharge_SW_HVS_47 "预充继电器驱动状态  备注：应用层的驱动指令信号";
CM_ SG_ 2332229487 ST_Main_POS_SW_HVS_47 "主正继电器驱动状态 备注：应用层的驱动指令信号";
CM_ SG_ 2332229487 ST_Main_NEG_SW_HVS_47 "主负继电器驱动状态 备注：应用层的驱动指令信号";
CM_ SG_ 2332229487 ST_System_47 "单柜是否允许上高压状态                                 未上高压前：0 为不允许上高压，1为允许上高压。上高压后：0为请求下高压，1为允许正常使用。";
CM_ SG_ 2332229487 ST_CALIBRATION_47 "单柜调试模式反馈                                   P2S调整报文发送（0x01 继电器指令，0x02 均衡指令，0x03 风机指令）信号的反馈状态，0是未接收相关的调试指令，1：接收到相关的调试指令";
CM_ SG_ 2332229487 ST_Insulation_47 "预留";
CM_ SG_ 2332229487 ST_PowerDown_47 "SBMU的供电输出低压电源状态                                                                           当前信号为低压相关的信号，发送的内部接口为：SeBMSM_LvPwrState 。含义为：SBMU低压电源运行状态反馈标志 ";
CM_ SG_ 2332229487 ST_pwr12V_47 "MCU反馈的12V电源pin应答状态";
CM_ SG_ 2332229487 ST_pwr5V_47 "预留";
CM_ SG_ 2332229487 ST_pwr24V_47 "通过MCU反馈的24V电源pin应答状态";
CM_ SG_ 2332229487 ST_pwrStatus_47 "单柜高压状态                                        当前为上高压完成信号：SbPRCC_HvPwrOnFinishFlg
 1,主正继电器的驱动指令为驱动闭合状态，且真实状态为闭合状态                                    2,主负继电器的驱动指令为驱动闭合状态，且真实状态为闭合状态                                     3, 预充继电器驱动指令为断开状态；                      同时满足条件1,2,3后保持1s 后该信号置为高压已上电
";
CM_ SG_ 2332229487 S2A_S2_FullChgFlgFromSBMU_47 "满充标志位";
CM_ SG_ 2332229487 ST_cscStandby_47 "CSC工作状态";
CM_ SG_ 2332229487 ST_OffReasonMsg_47 "主回路断开原因—每个bit代表一个原因，当前仅发送了前16个bit
 具体含义如下：
 Bit0: 高压无效Bit1:驱动短地Bit2:故障禁止上高压 forbid closeBit3:CSC编码中Bit4:概要数据中电压无效Bit5:概要数据温度无Bit6:预留调试模式（未使用）Bit7-Bit9: （未使用）Bit10: 未收到上高压指令Bit11: 故障强制断开继电器（force open）Bit12: 故障延迟断开继电器（normal Open）Bit13-Bit15: （未使用）";
CM_ SG_ 2332229488 CRC_S2A_S2_48 "S2A概要数据2 的CRC";
CM_ SG_ 2332229488 ALIV_ST_SW_HVS_48 "生命信号，0~15循环";
CM_ SG_ 2332229488 ST_PreCharge_SW_HVS_48 "预充继电器驱动状态  备注：应用层的驱动指令信号";
CM_ SG_ 2332229488 ST_Main_POS_SW_HVS_48 "主正继电器驱动状态 备注：应用层的驱动指令信号";
CM_ SG_ 2332229488 ST_Main_NEG_SW_HVS_48 "主负继电器驱动状态 备注：应用层的驱动指令信号";
CM_ SG_ 2332229488 ST_System_48 "单柜是否允许上高压状态                                 未上高压前：0 为不允许上高压，1为允许上高压。上高压后：0为请求下高压，1为允许正常使用。";
CM_ SG_ 2332229488 ST_CALIBRATION_48 "单柜调试模式反馈                                   P2S调整报文发送（0x01 继电器指令，0x02 均衡指令，0x03 风机指令）信号的反馈状态，0是未接收相关的调试指令，1：接收到相关的调试指令";
CM_ SG_ 2332229488 ST_Insulation_48 "预留";
CM_ SG_ 2332229488 ST_PowerDown_48 "SBMU的供电输出低压电源状态                                                                           当前信号为低压相关的信号，发送的内部接口为：SeBMSM_LvPwrState 。含义为：SBMU低压电源运行状态反馈标志 ";
CM_ SG_ 2332229488 ST_pwr12V_48 "MCU反馈的12V电源pin应答状态";
CM_ SG_ 2332229488 ST_pwr5V_48 "预留";
CM_ SG_ 2332229488 ST_pwr24V_48 "通过MCU反馈的24V电源pin应答状态";
CM_ SG_ 2332229488 ST_pwrStatus_48 "单柜高压状态                                        当前为上高压完成信号：SbPRCC_HvPwrOnFinishFlg
 1,主正继电器的驱动指令为驱动闭合状态，且真实状态为闭合状态                                    2,主负继电器的驱动指令为驱动闭合状态，且真实状态为闭合状态                                     3, 预充继电器驱动指令为断开状态；                      同时满足条件1,2,3后保持1s 后该信号置为高压已上电
";
CM_ SG_ 2332229488 S2A_S2_FullChgFlgFromSBMU_48 "满充标志位";
CM_ SG_ 2332229488 ST_cscStandby_48 "CSC工作状态";
CM_ SG_ 2332229488 ST_OffReasonMsg_48 "主回路断开原因—每个bit代表一个原因，当前仅发送了前16个bit
 具体含义如下：
 Bit0: 高压无效Bit1:驱动短地Bit2:故障禁止上高压 forbid closeBit3:CSC编码中Bit4:概要数据中电压无效Bit5:概要数据温度无Bit6:预留调试模式（未使用）Bit7-Bit9: （未使用）Bit10: 未收到上高压指令Bit11: 故障强制断开继电器（force open）Bit12: 故障延迟断开继电器（normal Open）Bit13-Bit15: （未使用）";
CM_ SG_ 2332229489 CRC_S2A_S2_49 "S2A概要数据2 的CRC";
CM_ SG_ 2332229489 ALIV_ST_SW_HVS_49 "生命信号，0~15循环";
CM_ SG_ 2332229489 ST_PreCharge_SW_HVS_49 "预充继电器驱动状态  备注：应用层的驱动指令信号";
CM_ SG_ 2332229489 ST_Main_POS_SW_HVS_49 "主正继电器驱动状态 备注：应用层的驱动指令信号";
CM_ SG_ 2332229489 ST_Main_NEG_SW_HVS_49 "主负继电器驱动状态 备注：应用层的驱动指令信号";
CM_ SG_ 2332229489 ST_System_49 "单柜是否允许上高压状态                                 未上高压前：0 为不允许上高压，1为允许上高压。上高压后：0为请求下高压，1为允许正常使用。";
CM_ SG_ 2332229489 ST_CALIBRATION_49 "单柜调试模式反馈                                   P2S调整报文发送（0x01 继电器指令，0x02 均衡指令，0x03 风机指令）信号的反馈状态，0是未接收相关的调试指令，1：接收到相关的调试指令";
CM_ SG_ 2332229489 ST_Insulation_49 "预留";
CM_ SG_ 2332229489 ST_PowerDown_49 "SBMU的供电输出低压电源状态                                                                           当前信号为低压相关的信号，发送的内部接口为：SeBMSM_LvPwrState 。含义为：SBMU低压电源运行状态反馈标志 ";
CM_ SG_ 2332229489 ST_pwr12V_49 "MCU反馈的12V电源pin应答状态";
CM_ SG_ 2332229489 ST_pwr5V_49 "预留";
CM_ SG_ 2332229489 ST_pwr24V_49 "通过MCU反馈的24V电源pin应答状态";
CM_ SG_ 2332229489 ST_pwrStatus_49 "单柜高压状态                                        当前为上高压完成信号：SbPRCC_HvPwrOnFinishFlg
 1,主正继电器的驱动指令为驱动闭合状态，且真实状态为闭合状态                                    2,主负继电器的驱动指令为驱动闭合状态，且真实状态为闭合状态                                     3, 预充继电器驱动指令为断开状态；                      同时满足条件1,2,3后保持1s 后该信号置为高压已上电
";
CM_ SG_ 2332229489 S2A_S2_FullChgFlgFromSBMU_49 "满充标志位";
CM_ SG_ 2332229489 ST_cscStandby_49 "CSC工作状态";
CM_ SG_ 2332229489 ST_OffReasonMsg_49 "主回路断开原因—每个bit代表一个原因，当前仅发送了前16个bit
 具体含义如下：
 Bit0: 高压无效Bit1:驱动短地Bit2:故障禁止上高压 forbid closeBit3:CSC编码中Bit4:概要数据中电压无效Bit5:概要数据温度无Bit6:预留调试模式（未使用）Bit7-Bit9: （未使用）Bit10: 未收到上高压指令Bit11: 故障强制断开继电器（force open）Bit12: 故障延迟断开继电器（normal Open）Bit13-Bit15: （未使用）";
CM_ SG_ 2332229490 CRC_S2A_S2_50 "S2A概要数据2 的CRC";
CM_ SG_ 2332229490 ALIV_ST_SW_HVS_50 "生命信号，0~15循环";
CM_ SG_ 2332229490 ST_PreCharge_SW_HVS_50 "预充继电器驱动状态  备注：应用层的驱动指令信号";
CM_ SG_ 2332229490 ST_Main_POS_SW_HVS_50 "主正继电器驱动状态 备注：应用层的驱动指令信号";
CM_ SG_ 2332229490 ST_Main_NEG_SW_HVS_50 "主负继电器驱动状态 备注：应用层的驱动指令信号";
CM_ SG_ 2332229490 ST_System_50 "单柜是否允许上高压状态                                 未上高压前：0 为不允许上高压，1为允许上高压。上高压后：0为请求下高压，1为允许正常使用。";
CM_ SG_ 2332229490 ST_CALIBRATION_50 "单柜调试模式反馈                                   P2S调整报文发送（0x01 继电器指令，0x02 均衡指令，0x03 风机指令）信号的反馈状态，0是未接收相关的调试指令，1：接收到相关的调试指令";
CM_ SG_ 2332229490 ST_Insulation_50 "预留";
CM_ SG_ 2332229490 ST_PowerDown_50 "SBMU的供电输出低压电源状态                                                                           当前信号为低压相关的信号，发送的内部接口为：SeBMSM_LvPwrState 。含义为：SBMU低压电源运行状态反馈标志 ";
CM_ SG_ 2332229490 ST_pwr12V_50 "MCU反馈的12V电源pin应答状态";
CM_ SG_ 2332229490 ST_pwr5V_50 "预留";
CM_ SG_ 2332229490 ST_pwr24V_50 "通过MCU反馈的24V电源pin应答状态";
CM_ SG_ 2332229490 ST_pwrStatus_50 "单柜高压状态                                        当前为上高压完成信号：SbPRCC_HvPwrOnFinishFlg
 1,主正继电器的驱动指令为驱动闭合状态，且真实状态为闭合状态                                    2,主负继电器的驱动指令为驱动闭合状态，且真实状态为闭合状态                                     3, 预充继电器驱动指令为断开状态；                      同时满足条件1,2,3后保持1s 后该信号置为高压已上电
";
CM_ SG_ 2332229490 S2A_S2_FullChgFlgFromSBMU_50 "满充标志位";
CM_ SG_ 2332229490 ST_cscStandby_50 "CSC工作状态";
CM_ SG_ 2332229490 ST_OffReasonMsg_50 "主回路断开原因—每个bit代表一个原因，当前仅发送了前16个bit
 具体含义如下：
 Bit0: 高压无效Bit1:驱动短地Bit2:故障禁止上高压 forbid closeBit3:CSC编码中Bit4:概要数据中电压无效Bit5:概要数据温度无Bit6:预留调试模式（未使用）Bit7-Bit9: （未使用）Bit10: 未收到上高压指令Bit11: 故障强制断开继电器（force open）Bit12: 故障延迟断开继电器（normal Open）Bit13-Bit15: （未使用）";
CM_ SG_ 2332229491 CRC_S2A_S2_51 "S2A概要数据2 的CRC";
CM_ SG_ 2332229491 ALIV_ST_SW_HVS_51 "生命信号，0~15循环";
CM_ SG_ 2332229491 ST_PreCharge_SW_HVS_51 "预充继电器驱动状态  备注：应用层的驱动指令信号";
CM_ SG_ 2332229491 ST_Main_POS_SW_HVS_51 "主正继电器驱动状态 备注：应用层的驱动指令信号";
CM_ SG_ 2332229491 ST_Main_NEG_SW_HVS_51 "主负继电器驱动状态 备注：应用层的驱动指令信号";
CM_ SG_ 2332229491 ST_System_51 "单柜是否允许上高压状态                                 未上高压前：0 为不允许上高压，1为允许上高压。上高压后：0为请求下高压，1为允许正常使用。";
CM_ SG_ 2332229491 ST_CALIBRATION_51 "单柜调试模式反馈                                   P2S调整报文发送（0x01 继电器指令，0x02 均衡指令，0x03 风机指令）信号的反馈状态，0是未接收相关的调试指令，1：接收到相关的调试指令";
CM_ SG_ 2332229491 ST_Insulation_51 "预留";
CM_ SG_ 2332229491 ST_PowerDown_51 "SBMU的供电输出低压电源状态                                                                           当前信号为低压相关的信号，发送的内部接口为：SeBMSM_LvPwrState 。含义为：SBMU低压电源运行状态反馈标志 ";
CM_ SG_ 2332229491 ST_pwr12V_51 "MCU反馈的12V电源pin应答状态";
CM_ SG_ 2332229491 ST_pwr5V_51 "预留";
CM_ SG_ 2332229491 ST_pwr24V_51 "通过MCU反馈的24V电源pin应答状态";
CM_ SG_ 2332229491 ST_pwrStatus_51 "单柜高压状态                                        当前为上高压完成信号：SbPRCC_HvPwrOnFinishFlg
 1,主正继电器的驱动指令为驱动闭合状态，且真实状态为闭合状态                                    2,主负继电器的驱动指令为驱动闭合状态，且真实状态为闭合状态                                     3, 预充继电器驱动指令为断开状态；                      同时满足条件1,2,3后保持1s 后该信号置为高压已上电
";
CM_ SG_ 2332229491 S2A_S2_FullChgFlgFromSBMU_51 "满充标志位";
CM_ SG_ 2332229491 ST_cscStandby_51 "CSC工作状态";
CM_ SG_ 2332229491 ST_OffReasonMsg_51 "主回路断开原因—每个bit代表一个原因，当前仅发送了前16个bit
 具体含义如下：
 Bit0: 高压无效Bit1:驱动短地Bit2:故障禁止上高压 forbid closeBit3:CSC编码中Bit4:概要数据中电压无效Bit5:概要数据温度无Bit6:预留调试模式（未使用）Bit7-Bit9: （未使用）Bit10: 未收到上高压指令Bit11: 故障强制断开继电器（force open）Bit12: 故障延迟断开继电器（normal Open）Bit13-Bit15: （未使用）";
CM_ SG_ 2332229492 CRC_S2A_S2_52 "S2A概要数据2 的CRC";
CM_ SG_ 2332229492 ALIV_ST_SW_HVS_52 "生命信号，0~15循环";
CM_ SG_ 2332229492 ST_PreCharge_SW_HVS_52 "预充继电器驱动状态  备注：应用层的驱动指令信号";
CM_ SG_ 2332229492 ST_Main_POS_SW_HVS_52 "主正继电器驱动状态 备注：应用层的驱动指令信号";
CM_ SG_ 2332229492 ST_Main_NEG_SW_HVS_52 "主负继电器驱动状态 备注：应用层的驱动指令信号";
CM_ SG_ 2332229492 ST_System_52 "单柜是否允许上高压状态                                 未上高压前：0 为不允许上高压，1为允许上高压。上高压后：0为请求下高压，1为允许正常使用。";
CM_ SG_ 2332229492 ST_CALIBRATION_52 "单柜调试模式反馈                                   P2S调整报文发送（0x01 继电器指令，0x02 均衡指令，0x03 风机指令）信号的反馈状态，0是未接收相关的调试指令，1：接收到相关的调试指令";
CM_ SG_ 2332229492 ST_Insulation_52 "预留";
CM_ SG_ 2332229492 ST_PowerDown_52 "SBMU的供电输出低压电源状态                                                                           当前信号为低压相关的信号，发送的内部接口为：SeBMSM_LvPwrState 。含义为：SBMU低压电源运行状态反馈标志 ";
CM_ SG_ 2332229492 ST_pwr12V_52 "MCU反馈的12V电源pin应答状态";
CM_ SG_ 2332229492 ST_pwr5V_52 "预留";
CM_ SG_ 2332229492 ST_pwr24V_52 "通过MCU反馈的24V电源pin应答状态";
CM_ SG_ 2332229492 ST_pwrStatus_52 "单柜高压状态                                        当前为上高压完成信号：SbPRCC_HvPwrOnFinishFlg
 1,主正继电器的驱动指令为驱动闭合状态，且真实状态为闭合状态                                    2,主负继电器的驱动指令为驱动闭合状态，且真实状态为闭合状态                                     3, 预充继电器驱动指令为断开状态；                      同时满足条件1,2,3后保持1s 后该信号置为高压已上电
";
CM_ SG_ 2332229492 S2A_S2_FullChgFlgFromSBMU_52 "满充标志位";
CM_ SG_ 2332229492 ST_cscStandby_52 "CSC工作状态";
CM_ SG_ 2332229492 ST_OffReasonMsg_52 "主回路断开原因—每个bit代表一个原因，当前仅发送了前16个bit
 具体含义如下：
 Bit0: 高压无效Bit1:驱动短地Bit2:故障禁止上高压 forbid closeBit3:CSC编码中Bit4:概要数据中电压无效Bit5:概要数据温度无Bit6:预留调试模式（未使用）Bit7-Bit9: （未使用）Bit10: 未收到上高压指令Bit11: 故障强制断开继电器（force open）Bit12: 故障延迟断开继电器（normal Open）Bit13-Bit15: （未使用）";
CM_ SG_ 2332229493 CRC_S2A_S2_53 "S2A概要数据2 的CRC";
CM_ SG_ 2332229493 ALIV_ST_SW_HVS_53 "生命信号，0~15循环";
CM_ SG_ 2332229493 ST_PreCharge_SW_HVS_53 "预充继电器驱动状态  备注：应用层的驱动指令信号";
CM_ SG_ 2332229493 ST_Main_POS_SW_HVS_53 "主正继电器驱动状态 备注：应用层的驱动指令信号";
CM_ SG_ 2332229493 ST_Main_NEG_SW_HVS_53 "主负继电器驱动状态 备注：应用层的驱动指令信号";
CM_ SG_ 2332229493 ST_System_53 "单柜是否允许上高压状态                                 未上高压前：0 为不允许上高压，1为允许上高压。上高压后：0为请求下高压，1为允许正常使用。";
CM_ SG_ 2332229493 ST_CALIBRATION_53 "单柜调试模式反馈                                   P2S调整报文发送（0x01 继电器指令，0x02 均衡指令，0x03 风机指令）信号的反馈状态，0是未接收相关的调试指令，1：接收到相关的调试指令";
CM_ SG_ 2332229493 ST_Insulation_53 "预留";
CM_ SG_ 2332229493 ST_PowerDown_53 "SBMU的供电输出低压电源状态                                                                           当前信号为低压相关的信号，发送的内部接口为：SeBMSM_LvPwrState 。含义为：SBMU低压电源运行状态反馈标志 ";
CM_ SG_ 2332229493 ST_pwr12V_53 "MCU反馈的12V电源pin应答状态";
CM_ SG_ 2332229493 ST_pwr5V_53 "预留";
CM_ SG_ 2332229493 ST_pwr24V_53 "通过MCU反馈的24V电源pin应答状态";
CM_ SG_ 2332229493 ST_pwrStatus_53 "单柜高压状态                                        当前为上高压完成信号：SbPRCC_HvPwrOnFinishFlg
 1,主正继电器的驱动指令为驱动闭合状态，且真实状态为闭合状态                                    2,主负继电器的驱动指令为驱动闭合状态，且真实状态为闭合状态                                     3, 预充继电器驱动指令为断开状态；                      同时满足条件1,2,3后保持1s 后该信号置为高压已上电
";
CM_ SG_ 2332229493 S2A_S2_FullChgFlgFromSBMU_53 "满充标志位";
CM_ SG_ 2332229493 ST_cscStandby_53 "CSC工作状态";
CM_ SG_ 2332229493 ST_OffReasonMsg_53 "主回路断开原因—每个bit代表一个原因，当前仅发送了前16个bit
 具体含义如下：
 Bit0: 高压无效Bit1:驱动短地Bit2:故障禁止上高压 forbid closeBit3:CSC编码中Bit4:概要数据中电压无效Bit5:概要数据温度无Bit6:预留调试模式（未使用）Bit7-Bit9: （未使用）Bit10: 未收到上高压指令Bit11: 故障强制断开继电器（force open）Bit12: 故障延迟断开继电器（normal Open）Bit13-Bit15: （未使用）";
CM_ SG_ 2332229494 CRC_S2A_S2_54 "S2A概要数据2 的CRC";
CM_ SG_ 2332229494 ALIV_ST_SW_HVS_54 "生命信号，0~15循环";
CM_ SG_ 2332229494 ST_PreCharge_SW_HVS_54 "预充继电器驱动状态  备注：应用层的驱动指令信号";
CM_ SG_ 2332229494 ST_Main_POS_SW_HVS_54 "主正继电器驱动状态 备注：应用层的驱动指令信号";
CM_ SG_ 2332229494 ST_Main_NEG_SW_HVS_54 "主负继电器驱动状态 备注：应用层的驱动指令信号";
CM_ SG_ 2332229494 ST_System_54 "单柜是否允许上高压状态                                 未上高压前：0 为不允许上高压，1为允许上高压。上高压后：0为请求下高压，1为允许正常使用。";
CM_ SG_ 2332229494 ST_CALIBRATION_54 "单柜调试模式反馈                                   P2S调整报文发送（0x01 继电器指令，0x02 均衡指令，0x03 风机指令）信号的反馈状态，0是未接收相关的调试指令，1：接收到相关的调试指令";
CM_ SG_ 2332229494 ST_Insulation_54 "预留";
CM_ SG_ 2332229494 ST_PowerDown_54 "SBMU的供电输出低压电源状态                                                                           当前信号为低压相关的信号，发送的内部接口为：SeBMSM_LvPwrState 。含义为：SBMU低压电源运行状态反馈标志 ";
CM_ SG_ 2332229494 ST_pwr12V_54 "MCU反馈的12V电源pin应答状态";
CM_ SG_ 2332229494 ST_pwr5V_54 "预留";
CM_ SG_ 2332229494 ST_pwr24V_54 "通过MCU反馈的24V电源pin应答状态";
CM_ SG_ 2332229494 ST_pwrStatus_54 "单柜高压状态                                        当前为上高压完成信号：SbPRCC_HvPwrOnFinishFlg
 1,主正继电器的驱动指令为驱动闭合状态，且真实状态为闭合状态                                    2,主负继电器的驱动指令为驱动闭合状态，且真实状态为闭合状态                                     3, 预充继电器驱动指令为断开状态；                      同时满足条件1,2,3后保持1s 后该信号置为高压已上电
";
CM_ SG_ 2332229494 S2A_S2_FullChgFlgFromSBMU_54 "满充标志位";
CM_ SG_ 2332229494 ST_cscStandby_54 "CSC工作状态";
CM_ SG_ 2332229494 ST_OffReasonMsg_54 "主回路断开原因—每个bit代表一个原因，当前仅发送了前16个bit
 具体含义如下：
 Bit0: 高压无效Bit1:驱动短地Bit2:故障禁止上高压 forbid closeBit3:CSC编码中Bit4:概要数据中电压无效Bit5:概要数据温度无Bit6:预留调试模式（未使用）Bit7-Bit9: （未使用）Bit10: 未收到上高压指令Bit11: 故障强制断开继电器（force open）Bit12: 故障延迟断开继电器（normal Open）Bit13-Bit15: （未使用）";
CM_ SG_ 2332229495 CRC_S2A_S2_55 "S2A概要数据2 的CRC";
CM_ SG_ 2332229495 ALIV_ST_SW_HVS_55 "生命信号，0~15循环";
CM_ SG_ 2332229495 ST_PreCharge_SW_HVS_55 "预充继电器驱动状态  备注：应用层的驱动指令信号";
CM_ SG_ 2332229495 ST_Main_POS_SW_HVS_55 "主正继电器驱动状态 备注：应用层的驱动指令信号";
CM_ SG_ 2332229495 ST_Main_NEG_SW_HVS_55 "主负继电器驱动状态 备注：应用层的驱动指令信号";
CM_ SG_ 2332229495 ST_System_55 "单柜是否允许上高压状态                                 未上高压前：0 为不允许上高压，1为允许上高压。上高压后：0为请求下高压，1为允许正常使用。";
CM_ SG_ 2332229495 ST_CALIBRATION_55 "单柜调试模式反馈                                   P2S调整报文发送（0x01 继电器指令，0x02 均衡指令，0x03 风机指令）信号的反馈状态，0是未接收相关的调试指令，1：接收到相关的调试指令";
CM_ SG_ 2332229495 ST_Insulation_55 "预留";
CM_ SG_ 2332229495 ST_PowerDown_55 "SBMU的供电输出低压电源状态                                                                           当前信号为低压相关的信号，发送的内部接口为：SeBMSM_LvPwrState 。含义为：SBMU低压电源运行状态反馈标志 ";
CM_ SG_ 2332229495 ST_pwr12V_55 "MCU反馈的12V电源pin应答状态";
CM_ SG_ 2332229495 ST_pwr5V_55 "预留";
CM_ SG_ 2332229495 ST_pwr24V_55 "通过MCU反馈的24V电源pin应答状态";
CM_ SG_ 2332229495 ST_pwrStatus_55 "单柜高压状态                                        当前为上高压完成信号：SbPRCC_HvPwrOnFinishFlg
 1,主正继电器的驱动指令为驱动闭合状态，且真实状态为闭合状态                                    2,主负继电器的驱动指令为驱动闭合状态，且真实状态为闭合状态                                     3, 预充继电器驱动指令为断开状态；                      同时满足条件1,2,3后保持1s 后该信号置为高压已上电
";
CM_ SG_ 2332229495 S2A_S2_FullChgFlgFromSBMU_55 "满充标志位";
CM_ SG_ 2332229495 ST_cscStandby_55 "CSC工作状态";
CM_ SG_ 2332229495 ST_OffReasonMsg_55 "主回路断开原因—每个bit代表一个原因，当前仅发送了前16个bit
 具体含义如下：
 Bit0: 高压无效Bit1:驱动短地Bit2:故障禁止上高压 forbid closeBit3:CSC编码中Bit4:概要数据中电压无效Bit5:概要数据温度无Bit6:预留调试模式（未使用）Bit7-Bit9: （未使用）Bit10: 未收到上高压指令Bit11: 故障强制断开继电器（force open）Bit12: 故障延迟断开继电器（normal Open）Bit13-Bit15: （未使用）";
CM_ SG_ 2332229496 CRC_S2A_S2_56 "S2A概要数据2 的CRC";
CM_ SG_ 2332229496 ALIV_ST_SW_HVS_56 "生命信号，0~15循环";
CM_ SG_ 2332229496 ST_PreCharge_SW_HVS_56 "预充继电器驱动状态  备注：应用层的驱动指令信号";
CM_ SG_ 2332229496 ST_Main_POS_SW_HVS_56 "主正继电器驱动状态 备注：应用层的驱动指令信号";
CM_ SG_ 2332229496 ST_Main_NEG_SW_HVS_56 "主负继电器驱动状态 备注：应用层的驱动指令信号";
CM_ SG_ 2332229496 ST_System_56 "单柜是否允许上高压状态                                 未上高压前：0 为不允许上高压，1为允许上高压。上高压后：0为请求下高压，1为允许正常使用。";
CM_ SG_ 2332229496 ST_CALIBRATION_56 "单柜调试模式反馈                                   P2S调整报文发送（0x01 继电器指令，0x02 均衡指令，0x03 风机指令）信号的反馈状态，0是未接收相关的调试指令，1：接收到相关的调试指令";
CM_ SG_ 2332229496 ST_Insulation_56 "预留";
CM_ SG_ 2332229496 ST_PowerDown_56 "SBMU的供电输出低压电源状态                                                                           当前信号为低压相关的信号，发送的内部接口为：SeBMSM_LvPwrState 。含义为：SBMU低压电源运行状态反馈标志 ";
CM_ SG_ 2332229496 ST_pwr12V_56 "MCU反馈的12V电源pin应答状态";
CM_ SG_ 2332229496 ST_pwr5V_56 "预留";
CM_ SG_ 2332229496 ST_pwr24V_56 "通过MCU反馈的24V电源pin应答状态";
CM_ SG_ 2332229496 ST_pwrStatus_56 "单柜高压状态                                        当前为上高压完成信号：SbPRCC_HvPwrOnFinishFlg
 1,主正继电器的驱动指令为驱动闭合状态，且真实状态为闭合状态                                    2,主负继电器的驱动指令为驱动闭合状态，且真实状态为闭合状态                                     3, 预充继电器驱动指令为断开状态；                      同时满足条件1,2,3后保持1s 后该信号置为高压已上电
";
CM_ SG_ 2332229496 S2A_S2_FullChgFlgFromSBMU_56 "满充标志位";
CM_ SG_ 2332229496 ST_cscStandby_56 "CSC工作状态";
CM_ SG_ 2332229496 ST_OffReasonMsg_56 "主回路断开原因—每个bit代表一个原因，当前仅发送了前16个bit
 具体含义如下：
 Bit0: 高压无效Bit1:驱动短地Bit2:故障禁止上高压 forbid closeBit3:CSC编码中Bit4:概要数据中电压无效Bit5:概要数据温度无Bit6:预留调试模式（未使用）Bit7-Bit9: （未使用）Bit10: 未收到上高压指令Bit11: 故障强制断开继电器（force open）Bit12: 故障延迟断开继电器（normal Open）Bit13-Bit15: （未使用）";
CM_ SG_ 2332229497 CRC_S2A_S2_57 "S2A概要数据2 的CRC";
CM_ SG_ 2332229497 ALIV_ST_SW_HVS_57 "生命信号，0~15循环";
CM_ SG_ 2332229497 ST_PreCharge_SW_HVS_57 "预充继电器驱动状态  备注：应用层的驱动指令信号";
CM_ SG_ 2332229497 ST_Main_POS_SW_HVS_57 "主正继电器驱动状态 备注：应用层的驱动指令信号";
CM_ SG_ 2332229497 ST_Main_NEG_SW_HVS_57 "主负继电器驱动状态 备注：应用层的驱动指令信号";
CM_ SG_ 2332229497 ST_System_57 "单柜是否允许上高压状态                                 未上高压前：0 为不允许上高压，1为允许上高压。上高压后：0为请求下高压，1为允许正常使用。";
CM_ SG_ 2332229497 ST_CALIBRATION_57 "单柜调试模式反馈                                   P2S调整报文发送（0x01 继电器指令，0x02 均衡指令，0x03 风机指令）信号的反馈状态，0是未接收相关的调试指令，1：接收到相关的调试指令";
CM_ SG_ 2332229497 ST_Insulation_57 "预留";
CM_ SG_ 2332229497 ST_PowerDown_57 "SBMU的供电输出低压电源状态                                                                           当前信号为低压相关的信号，发送的内部接口为：SeBMSM_LvPwrState 。含义为：SBMU低压电源运行状态反馈标志 ";
CM_ SG_ 2332229497 ST_pwr12V_57 "MCU反馈的12V电源pin应答状态";
CM_ SG_ 2332229497 ST_pwr5V_57 "预留";
CM_ SG_ 2332229497 ST_pwr24V_57 "通过MCU反馈的24V电源pin应答状态";
CM_ SG_ 2332229497 ST_pwrStatus_57 "单柜高压状态                                        当前为上高压完成信号：SbPRCC_HvPwrOnFinishFlg
 1,主正继电器的驱动指令为驱动闭合状态，且真实状态为闭合状态                                    2,主负继电器的驱动指令为驱动闭合状态，且真实状态为闭合状态                                     3, 预充继电器驱动指令为断开状态；                      同时满足条件1,2,3后保持1s 后该信号置为高压已上电
";
CM_ SG_ 2332229497 S2A_S2_FullChgFlgFromSBMU_57 "满充标志位";
CM_ SG_ 2332229497 ST_cscStandby_57 "CSC工作状态";
CM_ SG_ 2332229497 ST_OffReasonMsg_57 "主回路断开原因—每个bit代表一个原因，当前仅发送了前16个bit
 具体含义如下：
 Bit0: 高压无效Bit1:驱动短地Bit2:故障禁止上高压 forbid closeBit3:CSC编码中Bit4:概要数据中电压无效Bit5:概要数据温度无Bit6:预留调试模式（未使用）Bit7-Bit9: （未使用）Bit10: 未收到上高压指令Bit11: 故障强制断开继电器（force open）Bit12: 故障延迟断开继电器（normal Open）Bit13-Bit15: （未使用）";
CM_ SG_ 2332229498 CRC_S2A_S2_58 "S2A概要数据2 的CRC";
CM_ SG_ 2332229498 ALIV_ST_SW_HVS_58 "生命信号，0~15循环";
CM_ SG_ 2332229498 ST_PreCharge_SW_HVS_58 "预充继电器驱动状态  备注：应用层的驱动指令信号";
CM_ SG_ 2332229498 ST_Main_POS_SW_HVS_58 "主正继电器驱动状态 备注：应用层的驱动指令信号";
CM_ SG_ 2332229498 ST_Main_NEG_SW_HVS_58 "主负继电器驱动状态 备注：应用层的驱动指令信号";
CM_ SG_ 2332229498 ST_System_58 "单柜是否允许上高压状态                                 未上高压前：0 为不允许上高压，1为允许上高压。上高压后：0为请求下高压，1为允许正常使用。";
CM_ SG_ 2332229498 ST_CALIBRATION_58 "单柜调试模式反馈                                   P2S调整报文发送（0x01 继电器指令，0x02 均衡指令，0x03 风机指令）信号的反馈状态，0是未接收相关的调试指令，1：接收到相关的调试指令";
CM_ SG_ 2332229498 ST_Insulation_58 "预留";
CM_ SG_ 2332229498 ST_PowerDown_58 "SBMU的供电输出低压电源状态                                                                           当前信号为低压相关的信号，发送的内部接口为：SeBMSM_LvPwrState 。含义为：SBMU低压电源运行状态反馈标志 ";
CM_ SG_ 2332229498 ST_pwr12V_58 "MCU反馈的12V电源pin应答状态";
CM_ SG_ 2332229498 ST_pwr5V_58 "预留";
CM_ SG_ 2332229498 ST_pwr24V_58 "通过MCU反馈的24V电源pin应答状态";
CM_ SG_ 2332229498 ST_pwrStatus_58 "单柜高压状态                                        当前为上高压完成信号：SbPRCC_HvPwrOnFinishFlg
 1,主正继电器的驱动指令为驱动闭合状态，且真实状态为闭合状态                                    2,主负继电器的驱动指令为驱动闭合状态，且真实状态为闭合状态                                     3, 预充继电器驱动指令为断开状态；                      同时满足条件1,2,3后保持1s 后该信号置为高压已上电
";
CM_ SG_ 2332229498 S2A_S2_FullChgFlgFromSBMU_58 "满充标志位";
CM_ SG_ 2332229498 ST_cscStandby_58 "CSC工作状态";
CM_ SG_ 2332229498 ST_OffReasonMsg_58 "主回路断开原因—每个bit代表一个原因，当前仅发送了前16个bit
 具体含义如下：
 Bit0: 高压无效Bit1:驱动短地Bit2:故障禁止上高压 forbid closeBit3:CSC编码中Bit4:概要数据中电压无效Bit5:概要数据温度无Bit6:预留调试模式（未使用）Bit7-Bit9: （未使用）Bit10: 未收到上高压指令Bit11: 故障强制断开继电器（force open）Bit12: 故障延迟断开继电器（normal Open）Bit13-Bit15: （未使用）";
CM_ SG_ 2332229499 CRC_S2A_S2_59 "S2A概要数据2 的CRC";
CM_ SG_ 2332229499 ALIV_ST_SW_HVS_59 "生命信号，0~15循环";
CM_ SG_ 2332229499 ST_PreCharge_SW_HVS_59 "预充继电器驱动状态  备注：应用层的驱动指令信号";
CM_ SG_ 2332229499 ST_Main_POS_SW_HVS_59 "主正继电器驱动状态 备注：应用层的驱动指令信号";
CM_ SG_ 2332229499 ST_Main_NEG_SW_HVS_59 "主负继电器驱动状态 备注：应用层的驱动指令信号";
CM_ SG_ 2332229499 ST_System_59 "单柜是否允许上高压状态                                 未上高压前：0 为不允许上高压，1为允许上高压。上高压后：0为请求下高压，1为允许正常使用。";
CM_ SG_ 2332229499 ST_CALIBRATION_59 "单柜调试模式反馈                                   P2S调整报文发送（0x01 继电器指令，0x02 均衡指令，0x03 风机指令）信号的反馈状态，0是未接收相关的调试指令，1：接收到相关的调试指令";
CM_ SG_ 2332229499 ST_Insulation_59 "预留";
CM_ SG_ 2332229499 ST_PowerDown_59 "SBMU的供电输出低压电源状态                                                                           当前信号为低压相关的信号，发送的内部接口为：SeBMSM_LvPwrState 。含义为：SBMU低压电源运行状态反馈标志 ";
CM_ SG_ 2332229499 ST_pwr12V_59 "MCU反馈的12V电源pin应答状态";
CM_ SG_ 2332229499 ST_pwr5V_59 "预留";
CM_ SG_ 2332229499 ST_pwr24V_59 "通过MCU反馈的24V电源pin应答状态";
CM_ SG_ 2332229499 ST_pwrStatus_59 "单柜高压状态                                        当前为上高压完成信号：SbPRCC_HvPwrOnFinishFlg
 1,主正继电器的驱动指令为驱动闭合状态，且真实状态为闭合状态                                    2,主负继电器的驱动指令为驱动闭合状态，且真实状态为闭合状态                                     3, 预充继电器驱动指令为断开状态；                      同时满足条件1,2,3后保持1s 后该信号置为高压已上电
";
CM_ SG_ 2332229499 S2A_S2_FullChgFlgFromSBMU_59 "满充标志位";
CM_ SG_ 2332229499 ST_cscStandby_59 "CSC工作状态";
CM_ SG_ 2332229499 ST_OffReasonMsg_59 "主回路断开原因—每个bit代表一个原因，当前仅发送了前16个bit
 具体含义如下：
 Bit0: 高压无效Bit1:驱动短地Bit2:故障禁止上高压 forbid closeBit3:CSC编码中Bit4:概要数据中电压无效Bit5:概要数据温度无Bit6:预留调试模式（未使用）Bit7-Bit9: （未使用）Bit10: 未收到上高压指令Bit11: 故障强制断开继电器（force open）Bit12: 故障延迟断开继电器（normal Open）Bit13-Bit15: （未使用）";
CM_ SG_ 2332229500 CRC_S2A_S2_60 "S2A概要数据2 的CRC";
CM_ SG_ 2332229500 ALIV_ST_SW_HVS_60 "生命信号，0~15循环";
CM_ SG_ 2332229500 ST_PreCharge_SW_HVS_60 "预充继电器驱动状态  备注：应用层的驱动指令信号";
CM_ SG_ 2332229500 ST_Main_POS_SW_HVS_60 "主正继电器驱动状态 备注：应用层的驱动指令信号";
CM_ SG_ 2332229500 ST_Main_NEG_SW_HVS_60 "主负继电器驱动状态 备注：应用层的驱动指令信号";
CM_ SG_ 2332229500 ST_System_60 "单柜是否允许上高压状态                                 未上高压前：0 为不允许上高压，1为允许上高压。上高压后：0为请求下高压，1为允许正常使用。";
CM_ SG_ 2332229500 ST_CALIBRATION_60 "单柜调试模式反馈                                   P2S调整报文发送（0x01 继电器指令，0x02 均衡指令，0x03 风机指令）信号的反馈状态，0是未接收相关的调试指令，1：接收到相关的调试指令";
CM_ SG_ 2332229500 ST_Insulation_60 "预留";
CM_ SG_ 2332229500 ST_PowerDown_60 "SBMU的供电输出低压电源状态                                                                           当前信号为低压相关的信号，发送的内部接口为：SeBMSM_LvPwrState 。含义为：SBMU低压电源运行状态反馈标志 ";
CM_ SG_ 2332229500 ST_pwr12V_60 "MCU反馈的12V电源pin应答状态";
CM_ SG_ 2332229500 ST_pwr5V_60 "预留";
CM_ SG_ 2332229500 ST_pwr24V_60 "通过MCU反馈的24V电源pin应答状态";
CM_ SG_ 2332229500 ST_pwrStatus_60 "单柜高压状态                                        当前为上高压完成信号：SbPRCC_HvPwrOnFinishFlg
 1,主正继电器的驱动指令为驱动闭合状态，且真实状态为闭合状态                                    2,主负继电器的驱动指令为驱动闭合状态，且真实状态为闭合状态                                     3, 预充继电器驱动指令为断开状态；                      同时满足条件1,2,3后保持1s 后该信号置为高压已上电
";
CM_ SG_ 2332229500 S2A_S2_FullChgFlgFromSBMU_60 "满充标志位";
CM_ SG_ 2332229500 ST_cscStandby_60 "CSC工作状态";
CM_ SG_ 2332229500 ST_OffReasonMsg_60 "主回路断开原因—每个bit代表一个原因，当前仅发送了前16个bit
 具体含义如下：
 Bit0: 高压无效Bit1:驱动短地Bit2:故障禁止上高压 forbid closeBit3:CSC编码中Bit4:概要数据中电压无效Bit5:概要数据温度无Bit6:预留调试模式（未使用）Bit7-Bit9: （未使用）Bit10: 未收到上高压指令Bit11: 故障强制断开继电器（force open）Bit12: 故障延迟断开继电器（normal Open）Bit13-Bit15: （未使用）";
CM_ SG_ 2332229501 CRC_S2A_S2_61 "S2A概要数据2 的CRC";
CM_ SG_ 2332229501 ALIV_ST_SW_HVS_61 "生命信号，0~15循环";
CM_ SG_ 2332229501 ST_PreCharge_SW_HVS_61 "预充继电器驱动状态  备注：应用层的驱动指令信号";
CM_ SG_ 2332229501 ST_Main_POS_SW_HVS_61 "主正继电器驱动状态 备注：应用层的驱动指令信号";
CM_ SG_ 2332229501 ST_Main_NEG_SW_HVS_61 "主负继电器驱动状态 备注：应用层的驱动指令信号";
CM_ SG_ 2332229501 ST_System_61 "单柜是否允许上高压状态                                 未上高压前：0 为不允许上高压，1为允许上高压。上高压后：0为请求下高压，1为允许正常使用。";
CM_ SG_ 2332229501 ST_CALIBRATION_61 "单柜调试模式反馈                                   P2S调整报文发送（0x01 继电器指令，0x02 均衡指令，0x03 风机指令）信号的反馈状态，0是未接收相关的调试指令，1：接收到相关的调试指令";
CM_ SG_ 2332229501 ST_Insulation_61 "预留";
CM_ SG_ 2332229501 ST_PowerDown_61 "SBMU的供电输出低压电源状态                                                                           当前信号为低压相关的信号，发送的内部接口为：SeBMSM_LvPwrState 。含义为：SBMU低压电源运行状态反馈标志 ";
CM_ SG_ 2332229501 ST_pwr12V_61 "MCU反馈的12V电源pin应答状态";
CM_ SG_ 2332229501 ST_pwr5V_61 "预留";
CM_ SG_ 2332229501 ST_pwr24V_61 "通过MCU反馈的24V电源pin应答状态";
CM_ SG_ 2332229501 ST_pwrStatus_61 "单柜高压状态                                        当前为上高压完成信号：SbPRCC_HvPwrOnFinishFlg
 1,主正继电器的驱动指令为驱动闭合状态，且真实状态为闭合状态                                    2,主负继电器的驱动指令为驱动闭合状态，且真实状态为闭合状态                                     3, 预充继电器驱动指令为断开状态；                      同时满足条件1,2,3后保持1s 后该信号置为高压已上电
";
CM_ SG_ 2332229501 S2A_S2_FullChgFlgFromSBMU_61 "满充标志位";
CM_ SG_ 2332229501 ST_cscStandby_61 "CSC工作状态";
CM_ SG_ 2332229501 ST_OffReasonMsg_61 "主回路断开原因—每个bit代表一个原因，当前仅发送了前16个bit
 具体含义如下：
 Bit0: 高压无效Bit1:驱动短地Bit2:故障禁止上高压 forbid closeBit3:CSC编码中Bit4:概要数据中电压无效Bit5:概要数据温度无Bit6:预留调试模式（未使用）Bit7-Bit9: （未使用）Bit10: 未收到上高压指令Bit11: 故障强制断开继电器（force open）Bit12: 故障延迟断开继电器（normal Open）Bit13-Bit15: （未使用）";
CM_ SG_ 2332229502 CRC_S2A_S2_62 "S2A概要数据2 的CRC";
CM_ SG_ 2332229502 ALIV_ST_SW_HVS_62 "生命信号，0~15循环";
CM_ SG_ 2332229502 ST_PreCharge_SW_HVS_62 "预充继电器驱动状态  备注：应用层的驱动指令信号";
CM_ SG_ 2332229502 ST_Main_POS_SW_HVS_62 "主正继电器驱动状态 备注：应用层的驱动指令信号";
CM_ SG_ 2332229502 ST_Main_NEG_SW_HVS_62 "主负继电器驱动状态 备注：应用层的驱动指令信号";
CM_ SG_ 2332229502 ST_System_62 "单柜是否允许上高压状态                                 未上高压前：0 为不允许上高压，1为允许上高压。上高压后：0为请求下高压，1为允许正常使用。";
CM_ SG_ 2332229502 ST_CALIBRATION_62 "单柜调试模式反馈                                   P2S调整报文发送（0x01 继电器指令，0x02 均衡指令，0x03 风机指令）信号的反馈状态，0是未接收相关的调试指令，1：接收到相关的调试指令";
CM_ SG_ 2332229502 ST_Insulation_62 "预留";
CM_ SG_ 2332229502 ST_PowerDown_62 "SBMU的供电输出低压电源状态                                                                           当前信号为低压相关的信号，发送的内部接口为：SeBMSM_LvPwrState 。含义为：SBMU低压电源运行状态反馈标志 ";
CM_ SG_ 2332229502 ST_pwr12V_62 "MCU反馈的12V电源pin应答状态";
CM_ SG_ 2332229502 ST_pwr5V_62 "预留";
CM_ SG_ 2332229502 ST_pwr24V_62 "通过MCU反馈的24V电源pin应答状态";
CM_ SG_ 2332229502 ST_pwrStatus_62 "单柜高压状态                                        当前为上高压完成信号：SbPRCC_HvPwrOnFinishFlg
 1,主正继电器的驱动指令为驱动闭合状态，且真实状态为闭合状态                                    2,主负继电器的驱动指令为驱动闭合状态，且真实状态为闭合状态                                     3, 预充继电器驱动指令为断开状态；                      同时满足条件1,2,3后保持1s 后该信号置为高压已上电
";
CM_ SG_ 2332229502 S2A_S2_FullChgFlgFromSBMU_62 "满充标志位";
CM_ SG_ 2332229502 ST_cscStandby_62 "CSC工作状态";
CM_ SG_ 2332229502 ST_OffReasonMsg_62 "主回路断开原因—每个bit代表一个原因，当前仅发送了前16个bit
 具体含义如下：
 Bit0: 高压无效Bit1:驱动短地Bit2:故障禁止上高压 forbid closeBit3:CSC编码中Bit4:概要数据中电压无效Bit5:概要数据温度无Bit6:预留调试模式（未使用）Bit7-Bit9: （未使用）Bit10: 未收到上高压指令Bit11: 故障强制断开继电器（force open）Bit12: 故障延迟断开继电器（normal Open）Bit13-Bit15: （未使用）";
CM_ SG_ 2332229503 CRC_S2A_S2_63 "S2A概要数据2 的CRC";
CM_ SG_ 2332229503 ALIV_ST_SW_HVS_63 "生命信号，0~15循环";
CM_ SG_ 2332229503 ST_PreCharge_SW_HVS_63 "预充继电器驱动状态  备注：应用层的驱动指令信号";
CM_ SG_ 2332229503 ST_Main_POS_SW_HVS_63 "主正继电器驱动状态 备注：应用层的驱动指令信号";
CM_ SG_ 2332229503 ST_Main_NEG_SW_HVS_63 "主负继电器驱动状态 备注：应用层的驱动指令信号";
CM_ SG_ 2332229503 ST_System_63 "单柜是否允许上高压状态                                 未上高压前：0 为不允许上高压，1为允许上高压。上高压后：0为请求下高压，1为允许正常使用。";
CM_ SG_ 2332229503 ST_CALIBRATION_63 "单柜调试模式反馈                                   P2S调整报文发送（0x01 继电器指令，0x02 均衡指令，0x03 风机指令）信号的反馈状态，0是未接收相关的调试指令，1：接收到相关的调试指令";
CM_ SG_ 2332229503 ST_Insulation_63 "预留";
CM_ SG_ 2332229503 ST_PowerDown_63 "SBMU的供电输出低压电源状态                                                                           当前信号为低压相关的信号，发送的内部接口为：SeBMSM_LvPwrState 。含义为：SBMU低压电源运行状态反馈标志 ";
CM_ SG_ 2332229503 ST_pwr12V_63 "MCU反馈的12V电源pin应答状态";
CM_ SG_ 2332229503 ST_pwr5V_63 "预留";
CM_ SG_ 2332229503 ST_pwr24V_63 "通过MCU反馈的24V电源pin应答状态";
CM_ SG_ 2332229503 ST_pwrStatus_63 "单柜高压状态                                        当前为上高压完成信号：SbPRCC_HvPwrOnFinishFlg
 1,主正继电器的驱动指令为驱动闭合状态，且真实状态为闭合状态                                    2,主负继电器的驱动指令为驱动闭合状态，且真实状态为闭合状态                                     3, 预充继电器驱动指令为断开状态；                      同时满足条件1,2,3后保持1s 后该信号置为高压已上电
";
CM_ SG_ 2332229503 S2A_S2_FullChgFlgFromSBMU_63 "满充标志位";
CM_ SG_ 2332229503 ST_cscStandby_63 "CSC工作状态";
CM_ SG_ 2332229503 ST_OffReasonMsg_63 "主回路断开原因—每个bit代表一个原因，当前仅发送了前16个bit
 具体含义如下：
 Bit0: 高压无效Bit1:驱动短地Bit2:故障禁止上高压 forbid closeBit3:CSC编码中Bit4:概要数据中电压无效Bit5:概要数据温度无Bit6:预留调试模式（未使用）Bit7-Bit9: （未使用）Bit10: 未收到上高压指令Bit11: 故障强制断开继电器（force open）Bit12: 故障延迟断开继电器（normal Open）Bit13-Bit15: （未使用）";
CM_ SG_ 2332294977 CRC_S2A_S3_01 "S2A概要数据3 的CRC";
CM_ SG_ 2332294977 BAT_Ucell_Max_CSC_01 "最高单体电压所在CSC号(当前最大支持63个)从1开始";
CM_ SG_ 2332294977 BAT_Ucell_Max_CELL_01 "最高单体电压所在电芯位置（当前最大位号63）从1开始";
CM_ SG_ 2332294977 BAT_Ucell_Min_CSC_01 "最低单体电压所在CSC号(当前最大支持个数63个)从1开始";
CM_ SG_ 2332294977 BAT_Ucell_Min_CELL_01 "最低单体电压所在电芯位置（当前最大位号63）从1开始";
CM_ SG_ 2332294977 BAT_Ucell_Max_01 "最高单体电压";
CM_ SG_ 2332294977 BAT_Ucell_Min_01 "最低单体电压";
CM_ SG_ 2332294978 CRC_S2A_S3_02 "S2A概要数据3 的CRC";
CM_ SG_ 2332294978 BAT_Ucell_Max_CSC_02 "最高单体电压所在CSC号(当前最大支持63个)从1开始";
CM_ SG_ 2332294978 BAT_Ucell_Max_CELL_02 "最高单体电压所在电芯位置（当前最大位号63）从1开始";
CM_ SG_ 2332294978 BAT_Ucell_Min_CSC_02 "最低单体电压所在CSC号(当前最大支持个数63个)从1开始";
CM_ SG_ 2332294978 BAT_Ucell_Min_CELL_02 "最低单体电压所在电芯位置（当前最大位号63）从1开始";
CM_ SG_ 2332294978 BAT_Ucell_Max_02 "最高单体电压";
CM_ SG_ 2332294978 BAT_Ucell_Min_02 "最低单体电压";
CM_ SG_ 2332294979 CRC_S2A_S3_03 "S2A概要数据3 的CRC";
CM_ SG_ 2332294979 BAT_Ucell_Max_CSC_03 "最高单体电压所在CSC号(当前最大支持63个)从1开始";
CM_ SG_ 2332294979 BAT_Ucell_Max_CELL_03 "最高单体电压所在电芯位置（当前最大位号63）从1开始";
CM_ SG_ 2332294979 BAT_Ucell_Min_CSC_03 "最低单体电压所在CSC号(当前最大支持个数63个)从1开始";
CM_ SG_ 2332294979 BAT_Ucell_Min_CELL_03 "最低单体电压所在电芯位置（当前最大位号63）从1开始";
CM_ SG_ 2332294979 BAT_Ucell_Max_03 "最高单体电压";
CM_ SG_ 2332294979 BAT_Ucell_Min_03 "最低单体电压";
CM_ SG_ 2332294980 CRC_S2A_S3_04 "S2A概要数据3 的CRC";
CM_ SG_ 2332294980 BAT_Ucell_Max_CSC_04 "最高单体电压所在CSC号(当前最大支持63个)从1开始";
CM_ SG_ 2332294980 BAT_Ucell_Max_CELL_04 "最高单体电压所在电芯位置（当前最大位号63）从1开始";
CM_ SG_ 2332294980 BAT_Ucell_Min_CSC_04 "最低单体电压所在CSC号(当前最大支持个数63个)从1开始";
CM_ SG_ 2332294980 BAT_Ucell_Min_CELL_04 "最低单体电压所在电芯位置（当前最大位号63）从1开始";
CM_ SG_ 2332294980 BAT_Ucell_Max_04 "最高单体电压";
CM_ SG_ 2332294980 BAT_Ucell_Min_04 "最低单体电压";
CM_ SG_ 2332294981 CRC_S2A_S3_05 "S2A概要数据3 的CRC";
CM_ SG_ 2332294981 BAT_Ucell_Max_CSC_05 "最高单体电压所在CSC号(当前最大支持63个)从1开始";
CM_ SG_ 2332294981 BAT_Ucell_Max_CELL_05 "最高单体电压所在电芯位置（当前最大位号63）从1开始";
CM_ SG_ 2332294981 BAT_Ucell_Min_CSC_05 "最低单体电压所在CSC号(当前最大支持个数63个)从1开始";
CM_ SG_ 2332294981 BAT_Ucell_Min_CELL_05 "最低单体电压所在电芯位置（当前最大位号63）从1开始";
CM_ SG_ 2332294981 BAT_Ucell_Max_05 "最高单体电压";
CM_ SG_ 2332294981 BAT_Ucell_Min_05 "最低单体电压";
CM_ SG_ 2332294982 CRC_S2A_S3_06 "S2A概要数据3 的CRC";
CM_ SG_ 2332294982 BAT_Ucell_Max_CSC_06 "最高单体电压所在CSC号(当前最大支持63个)从1开始";
CM_ SG_ 2332294982 BAT_Ucell_Max_CELL_06 "最高单体电压所在电芯位置（当前最大位号63）从1开始";
CM_ SG_ 2332294982 BAT_Ucell_Min_CSC_06 "最低单体电压所在CSC号(当前最大支持个数63个)从1开始";
CM_ SG_ 2332294982 BAT_Ucell_Min_CELL_06 "最低单体电压所在电芯位置（当前最大位号63）从1开始";
CM_ SG_ 2332294982 BAT_Ucell_Max_06 "最高单体电压";
CM_ SG_ 2332294982 BAT_Ucell_Min_06 "最低单体电压";
CM_ SG_ 2332294983 CRC_S2A_S3_07 "S2A概要数据3 的CRC";
CM_ SG_ 2332294983 BAT_Ucell_Max_CSC_07 "最高单体电压所在CSC号(当前最大支持63个)从1开始";
CM_ SG_ 2332294983 BAT_Ucell_Max_CELL_07 "最高单体电压所在电芯位置（当前最大位号63）从1开始";
CM_ SG_ 2332294983 BAT_Ucell_Min_CSC_07 "最低单体电压所在CSC号(当前最大支持个数63个)从1开始";
CM_ SG_ 2332294983 BAT_Ucell_Min_CELL_07 "最低单体电压所在电芯位置（当前最大位号63）从1开始";
CM_ SG_ 2332294983 BAT_Ucell_Max_07 "最高单体电压";
CM_ SG_ 2332294983 BAT_Ucell_Min_07 "最低单体电压";
CM_ SG_ 2332294984 CRC_S2A_S3_08 "S2A概要数据3 的CRC";
CM_ SG_ 2332294984 BAT_Ucell_Max_CSC_08 "最高单体电压所在CSC号(当前最大支持63个)从1开始";
CM_ SG_ 2332294984 BAT_Ucell_Max_CELL_08 "最高单体电压所在电芯位置（当前最大位号63）从1开始";
CM_ SG_ 2332294984 BAT_Ucell_Min_CSC_08 "最低单体电压所在CSC号(当前最大支持个数63个)从1开始";
CM_ SG_ 2332294984 BAT_Ucell_Min_CELL_08 "最低单体电压所在电芯位置（当前最大位号63）从1开始";
CM_ SG_ 2332294984 BAT_Ucell_Max_08 "最高单体电压";
CM_ SG_ 2332294984 BAT_Ucell_Min_08 "最低单体电压";
CM_ SG_ 2332294985 CRC_S2A_S3_09 "S2A概要数据3 的CRC";
CM_ SG_ 2332294985 BAT_Ucell_Max_CSC_09 "最高单体电压所在CSC号(当前最大支持63个)从1开始";
CM_ SG_ 2332294985 BAT_Ucell_Max_CELL_09 "最高单体电压所在电芯位置（当前最大位号63）从1开始";
CM_ SG_ 2332294985 BAT_Ucell_Min_CSC_09 "最低单体电压所在CSC号(当前最大支持个数63个)从1开始";
CM_ SG_ 2332294985 BAT_Ucell_Min_CELL_09 "最低单体电压所在电芯位置（当前最大位号63）从1开始";
CM_ SG_ 2332294985 BAT_Ucell_Max_09 "最高单体电压";
CM_ SG_ 2332294985 BAT_Ucell_Min_09 "最低单体电压";
CM_ SG_ 2332294986 CRC_S2A_S3_10 "S2A概要数据3 的CRC";
CM_ SG_ 2332294986 BAT_Ucell_Max_CSC_10 "最高单体电压所在CSC号(当前最大支持63个)从1开始";
CM_ SG_ 2332294986 BAT_Ucell_Max_CELL_10 "最高单体电压所在电芯位置（当前最大位号63）从1开始";
CM_ SG_ 2332294986 BAT_Ucell_Min_CSC_10 "最低单体电压所在CSC号(当前最大支持个数63个)从1开始";
CM_ SG_ 2332294986 BAT_Ucell_Min_CELL_10 "最低单体电压所在电芯位置（当前最大位号63）从1开始";
CM_ SG_ 2332294986 BAT_Ucell_Max_10 "最高单体电压";
CM_ SG_ 2332294986 BAT_Ucell_Min_10 "最低单体电压";
CM_ SG_ 2332294987 CRC_S2A_S3_11 "S2A概要数据3 的CRC";
CM_ SG_ 2332294987 BAT_Ucell_Max_CSC_11 "最高单体电压所在CSC号(当前最大支持63个)从1开始";
CM_ SG_ 2332294987 BAT_Ucell_Max_CELL_11 "最高单体电压所在电芯位置（当前最大位号63）从1开始";
CM_ SG_ 2332294987 BAT_Ucell_Min_CSC_11 "最低单体电压所在CSC号(当前最大支持个数63个)从1开始";
CM_ SG_ 2332294987 BAT_Ucell_Min_CELL_11 "最低单体电压所在电芯位置（当前最大位号63）从1开始";
CM_ SG_ 2332294987 BAT_Ucell_Max_11 "最高单体电压";
CM_ SG_ 2332294987 BAT_Ucell_Min_11 "最低单体电压";
CM_ SG_ 2332294988 CRC_S2A_S3_12 "S2A概要数据3 的CRC";
CM_ SG_ 2332294988 BAT_Ucell_Max_CSC_12 "最高单体电压所在CSC号(当前最大支持63个)从1开始";
CM_ SG_ 2332294988 BAT_Ucell_Max_CELL_12 "最高单体电压所在电芯位置（当前最大位号63）从1开始";
CM_ SG_ 2332294988 BAT_Ucell_Min_CSC_12 "最低单体电压所在CSC号(当前最大支持个数63个)从1开始";
CM_ SG_ 2332294988 BAT_Ucell_Min_CELL_12 "最低单体电压所在电芯位置（当前最大位号63）从1开始";
CM_ SG_ 2332294988 BAT_Ucell_Max_12 "最高单体电压";
CM_ SG_ 2332294988 BAT_Ucell_Min_12 "最低单体电压";
CM_ SG_ 2332294989 CRC_S2A_S3_13 "S2A概要数据3 的CRC";
CM_ SG_ 2332294989 BAT_Ucell_Max_CSC_13 "最高单体电压所在CSC号(当前最大支持63个)从1开始";
CM_ SG_ 2332294989 BAT_Ucell_Max_CELL_13 "最高单体电压所在电芯位置（当前最大位号63）从1开始";
CM_ SG_ 2332294989 BAT_Ucell_Min_CSC_13 "最低单体电压所在CSC号(当前最大支持个数63个)从1开始";
CM_ SG_ 2332294989 BAT_Ucell_Min_CELL_13 "最低单体电压所在电芯位置（当前最大位号63）从1开始";
CM_ SG_ 2332294989 BAT_Ucell_Max_13 "最高单体电压";
CM_ SG_ 2332294989 BAT_Ucell_Min_13 "最低单体电压";
CM_ SG_ 2332294990 CRC_S2A_S3_14 "S2A概要数据3 的CRC";
CM_ SG_ 2332294990 BAT_Ucell_Max_CSC_14 "最高单体电压所在CSC号(当前最大支持63个)从1开始";
CM_ SG_ 2332294990 BAT_Ucell_Max_CELL_14 "最高单体电压所在电芯位置（当前最大位号63）从1开始";
CM_ SG_ 2332294990 BAT_Ucell_Min_CSC_14 "最低单体电压所在CSC号(当前最大支持个数63个)从1开始";
CM_ SG_ 2332294990 BAT_Ucell_Min_CELL_14 "最低单体电压所在电芯位置（当前最大位号63）从1开始";
CM_ SG_ 2332294990 BAT_Ucell_Max_14 "最高单体电压";
CM_ SG_ 2332294990 BAT_Ucell_Min_14 "最低单体电压";
CM_ SG_ 2332294991 CRC_S2A_S3_15 "S2A概要数据3 的CRC";
CM_ SG_ 2332294991 BAT_Ucell_Max_CSC_15 "最高单体电压所在CSC号(当前最大支持63个)从1开始";
CM_ SG_ 2332294991 BAT_Ucell_Max_CELL_15 "最高单体电压所在电芯位置（当前最大位号63）从1开始";
CM_ SG_ 2332294991 BAT_Ucell_Min_CSC_15 "最低单体电压所在CSC号(当前最大支持个数63个)从1开始";
CM_ SG_ 2332294991 BAT_Ucell_Min_CELL_15 "最低单体电压所在电芯位置（当前最大位号63）从1开始";
CM_ SG_ 2332294991 BAT_Ucell_Max_15 "最高单体电压";
CM_ SG_ 2332294991 BAT_Ucell_Min_15 "最低单体电压";
CM_ SG_ 2332294992 CRC_S2A_S3_16 "S2A概要数据3 的CRC";
CM_ SG_ 2332294992 BAT_Ucell_Max_CSC_16 "最高单体电压所在CSC号(当前最大支持63个)从1开始";
CM_ SG_ 2332294992 BAT_Ucell_Max_CELL_16 "最高单体电压所在电芯位置（当前最大位号63）从1开始";
CM_ SG_ 2332294992 BAT_Ucell_Min_CSC_16 "最低单体电压所在CSC号(当前最大支持个数63个)从1开始";
CM_ SG_ 2332294992 BAT_Ucell_Min_CELL_16 "最低单体电压所在电芯位置（当前最大位号63）从1开始";
CM_ SG_ 2332294992 BAT_Ucell_Max_16 "最高单体电压";
CM_ SG_ 2332294992 BAT_Ucell_Min_16 "最低单体电压";
CM_ SG_ 2332294993 CRC_S2A_S3_17 "S2A概要数据3 的CRC";
CM_ SG_ 2332294993 BAT_Ucell_Max_CSC_17 "最高单体电压所在CSC号(当前最大支持63个)从1开始";
CM_ SG_ 2332294993 BAT_Ucell_Max_CELL_17 "最高单体电压所在电芯位置（当前最大位号63）从1开始";
CM_ SG_ 2332294993 BAT_Ucell_Min_CSC_17 "最低单体电压所在CSC号(当前最大支持个数63个)从1开始";
CM_ SG_ 2332294993 BAT_Ucell_Min_CELL_17 "最低单体电压所在电芯位置（当前最大位号63）从1开始";
CM_ SG_ 2332294993 BAT_Ucell_Max_17 "最高单体电压";
CM_ SG_ 2332294993 BAT_Ucell_Min_17 "最低单体电压";
CM_ SG_ 2332294994 CRC_S2A_S3_18 "S2A概要数据3 的CRC";
CM_ SG_ 2332294994 BAT_Ucell_Max_CSC_18 "最高单体电压所在CSC号(当前最大支持63个)从1开始";
CM_ SG_ 2332294994 BAT_Ucell_Max_CELL_18 "最高单体电压所在电芯位置（当前最大位号63）从1开始";
CM_ SG_ 2332294994 BAT_Ucell_Min_CSC_18 "最低单体电压所在CSC号(当前最大支持个数63个)从1开始";
CM_ SG_ 2332294994 BAT_Ucell_Min_CELL_18 "最低单体电压所在电芯位置（当前最大位号63）从1开始";
CM_ SG_ 2332294994 BAT_Ucell_Max_18 "最高单体电压";
CM_ SG_ 2332294994 BAT_Ucell_Min_18 "最低单体电压";
CM_ SG_ 2332294995 CRC_S2A_S3_19 "S2A概要数据3 的CRC";
CM_ SG_ 2332294995 BAT_Ucell_Max_CSC_19 "最高单体电压所在CSC号(当前最大支持63个)从1开始";
CM_ SG_ 2332294995 BAT_Ucell_Max_CELL_19 "最高单体电压所在电芯位置（当前最大位号63）从1开始";
CM_ SG_ 2332294995 BAT_Ucell_Min_CSC_19 "最低单体电压所在CSC号(当前最大支持个数63个)从1开始";
CM_ SG_ 2332294995 BAT_Ucell_Min_CELL_19 "最低单体电压所在电芯位置（当前最大位号63）从1开始";
CM_ SG_ 2332294995 BAT_Ucell_Max_19 "最高单体电压";
CM_ SG_ 2332294995 BAT_Ucell_Min_19 "最低单体电压";
CM_ SG_ 2332294996 CRC_S2A_S3_20 "S2A概要数据3 的CRC";
CM_ SG_ 2332294996 BAT_Ucell_Max_CSC_20 "最高单体电压所在CSC号(当前最大支持63个)从1开始";
CM_ SG_ 2332294996 BAT_Ucell_Max_CELL_20 "最高单体电压所在电芯位置（当前最大位号63）从1开始";
CM_ SG_ 2332294996 BAT_Ucell_Min_CSC_20 "最低单体电压所在CSC号(当前最大支持个数63个)从1开始";
CM_ SG_ 2332294996 BAT_Ucell_Min_CELL_20 "最低单体电压所在电芯位置（当前最大位号63）从1开始";
CM_ SG_ 2332294996 BAT_Ucell_Max_20 "最高单体电压";
CM_ SG_ 2332294996 BAT_Ucell_Min_20 "最低单体电压";
CM_ SG_ 2332294997 CRC_S2A_S3_21 "S2A概要数据3 的CRC";
CM_ SG_ 2332294997 BAT_Ucell_Max_CSC_21 "最高单体电压所在CSC号(当前最大支持63个)从1开始";
CM_ SG_ 2332294997 BAT_Ucell_Max_CELL_21 "最高单体电压所在电芯位置（当前最大位号63）从1开始";
CM_ SG_ 2332294997 BAT_Ucell_Min_CSC_21 "最低单体电压所在CSC号(当前最大支持个数63个)从1开始";
CM_ SG_ 2332294997 BAT_Ucell_Min_CELL_21 "最低单体电压所在电芯位置（当前最大位号63）从1开始";
CM_ SG_ 2332294997 BAT_Ucell_Max_21 "最高单体电压";
CM_ SG_ 2332294997 BAT_Ucell_Min_21 "最低单体电压";
CM_ SG_ 2332294998 CRC_S2A_S3_22 "S2A概要数据3 的CRC";
CM_ SG_ 2332294998 BAT_Ucell_Max_CSC_22 "最高单体电压所在CSC号(当前最大支持63个)从1开始";
CM_ SG_ 2332294998 BAT_Ucell_Max_CELL_22 "最高单体电压所在电芯位置（当前最大位号63）从1开始";
CM_ SG_ 2332294998 BAT_Ucell_Min_CSC_22 "最低单体电压所在CSC号(当前最大支持个数63个)从1开始";
CM_ SG_ 2332294998 BAT_Ucell_Min_CELL_22 "最低单体电压所在电芯位置（当前最大位号63）从1开始";
CM_ SG_ 2332294998 BAT_Ucell_Max_22 "最高单体电压";
CM_ SG_ 2332294998 BAT_Ucell_Min_22 "最低单体电压";
CM_ SG_ 2332294999 CRC_S2A_S3_23 "S2A概要数据3 的CRC";
CM_ SG_ 2332294999 BAT_Ucell_Max_CSC_23 "最高单体电压所在CSC号(当前最大支持63个)从1开始";
CM_ SG_ 2332294999 BAT_Ucell_Max_CELL_23 "最高单体电压所在电芯位置（当前最大位号63）从1开始";
CM_ SG_ 2332294999 BAT_Ucell_Min_CSC_23 "最低单体电压所在CSC号(当前最大支持个数63个)从1开始";
CM_ SG_ 2332294999 BAT_Ucell_Min_CELL_23 "最低单体电压所在电芯位置（当前最大位号63）从1开始";
CM_ SG_ 2332294999 BAT_Ucell_Max_23 "最高单体电压";
CM_ SG_ 2332294999 BAT_Ucell_Min_23 "最低单体电压";
CM_ SG_ 2332295000 CRC_S2A_S3_24 "S2A概要数据3 的CRC";
CM_ SG_ 2332295000 BAT_Ucell_Max_CSC_24 "最高单体电压所在CSC号(当前最大支持63个)从1开始";
CM_ SG_ 2332295000 BAT_Ucell_Max_CELL_24 "最高单体电压所在电芯位置（当前最大位号63）从1开始";
CM_ SG_ 2332295000 BAT_Ucell_Min_CSC_24 "最低单体电压所在CSC号(当前最大支持个数63个)从1开始";
CM_ SG_ 2332295000 BAT_Ucell_Min_CELL_24 "最低单体电压所在电芯位置（当前最大位号63）从1开始";
CM_ SG_ 2332295000 BAT_Ucell_Max_24 "最高单体电压";
CM_ SG_ 2332295000 BAT_Ucell_Min_24 "最低单体电压";
CM_ SG_ 2332295001 CRC_S2A_S3_25 "S2A概要数据3 的CRC";
CM_ SG_ 2332295001 BAT_Ucell_Max_CSC_25 "最高单体电压所在CSC号(当前最大支持63个)从1开始";
CM_ SG_ 2332295001 BAT_Ucell_Max_CELL_25 "最高单体电压所在电芯位置（当前最大位号63）从1开始";
CM_ SG_ 2332295001 BAT_Ucell_Min_CSC_25 "最低单体电压所在CSC号(当前最大支持个数63个)从1开始";
CM_ SG_ 2332295001 BAT_Ucell_Min_CELL_25 "最低单体电压所在电芯位置（当前最大位号63）从1开始";
CM_ SG_ 2332295001 BAT_Ucell_Max_25 "最高单体电压";
CM_ SG_ 2332295001 BAT_Ucell_Min_25 "最低单体电压";
CM_ SG_ 2332295002 CRC_S2A_S3_26 "S2A概要数据3 的CRC";
CM_ SG_ 2332295002 BAT_Ucell_Max_CSC_26 "最高单体电压所在CSC号(当前最大支持63个)从1开始";
CM_ SG_ 2332295002 BAT_Ucell_Max_CELL_26 "最高单体电压所在电芯位置（当前最大位号63）从1开始";
CM_ SG_ 2332295002 BAT_Ucell_Min_CSC_26 "最低单体电压所在CSC号(当前最大支持个数63个)从1开始";
CM_ SG_ 2332295002 BAT_Ucell_Min_CELL_26 "最低单体电压所在电芯位置（当前最大位号63）从1开始";
CM_ SG_ 2332295002 BAT_Ucell_Max_26 "最高单体电压";
CM_ SG_ 2332295002 BAT_Ucell_Min_26 "最低单体电压";
CM_ SG_ 2332295003 CRC_S2A_S3_27 "S2A概要数据3 的CRC";
CM_ SG_ 2332295003 BAT_Ucell_Max_CSC_27 "最高单体电压所在CSC号(当前最大支持63个)从1开始";
CM_ SG_ 2332295003 BAT_Ucell_Max_CELL_27 "最高单体电压所在电芯位置（当前最大位号63）从1开始";
CM_ SG_ 2332295003 BAT_Ucell_Min_CSC_27 "最低单体电压所在CSC号(当前最大支持个数63个)从1开始";
CM_ SG_ 2332295003 BAT_Ucell_Min_CELL_27 "最低单体电压所在电芯位置（当前最大位号63）从1开始";
CM_ SG_ 2332295003 BAT_Ucell_Max_27 "最高单体电压";
CM_ SG_ 2332295003 BAT_Ucell_Min_27 "最低单体电压";
CM_ SG_ 2332295004 CRC_S2A_S3_28 "S2A概要数据3 的CRC";
CM_ SG_ 2332295004 BAT_Ucell_Max_CSC_28 "最高单体电压所在CSC号(当前最大支持63个)从1开始";
CM_ SG_ 2332295004 BAT_Ucell_Max_CELL_28 "最高单体电压所在电芯位置（当前最大位号63）从1开始";
CM_ SG_ 2332295004 BAT_Ucell_Min_CSC_28 "最低单体电压所在CSC号(当前最大支持个数63个)从1开始";
CM_ SG_ 2332295004 BAT_Ucell_Min_CELL_28 "最低单体电压所在电芯位置（当前最大位号63）从1开始";
CM_ SG_ 2332295004 BAT_Ucell_Max_28 "最高单体电压";
CM_ SG_ 2332295004 BAT_Ucell_Min_28 "最低单体电压";
CM_ SG_ 2332295005 CRC_S2A_S3_29 "S2A概要数据3 的CRC";
CM_ SG_ 2332295005 BAT_Ucell_Max_CSC_29 "最高单体电压所在CSC号(当前最大支持63个)从1开始";
CM_ SG_ 2332295005 BAT_Ucell_Max_CELL_29 "最高单体电压所在电芯位置（当前最大位号63）从1开始";
CM_ SG_ 2332295005 BAT_Ucell_Min_CSC_29 "最低单体电压所在CSC号(当前最大支持个数63个)从1开始";
CM_ SG_ 2332295005 BAT_Ucell_Min_CELL_29 "最低单体电压所在电芯位置（当前最大位号63）从1开始";
CM_ SG_ 2332295005 BAT_Ucell_Max_29 "最高单体电压";
CM_ SG_ 2332295005 BAT_Ucell_Min_29 "最低单体电压";
CM_ SG_ 2332295006 CRC_S2A_S3_30 "S2A概要数据3 的CRC";
CM_ SG_ 2332295006 BAT_Ucell_Max_CSC_30 "最高单体电压所在CSC号(当前最大支持63个)从1开始";
CM_ SG_ 2332295006 BAT_Ucell_Max_CELL_30 "最高单体电压所在电芯位置（当前最大位号63）从1开始";
CM_ SG_ 2332295006 BAT_Ucell_Min_CSC_30 "最低单体电压所在CSC号(当前最大支持个数63个)从1开始";
CM_ SG_ 2332295006 BAT_Ucell_Min_CELL_30 "最低单体电压所在电芯位置（当前最大位号63）从1开始";
CM_ SG_ 2332295006 BAT_Ucell_Max_30 "最高单体电压";
CM_ SG_ 2332295006 BAT_Ucell_Min_30 "最低单体电压";
CM_ SG_ 2332295007 CRC_S2A_S3_31 "S2A概要数据3 的CRC";
CM_ SG_ 2332295007 BAT_Ucell_Max_CSC_31 "最高单体电压所在CSC号(当前最大支持63个)从1开始";
CM_ SG_ 2332295007 BAT_Ucell_Max_CELL_31 "最高单体电压所在电芯位置（当前最大位号63）从1开始";
CM_ SG_ 2332295007 BAT_Ucell_Min_CSC_31 "最低单体电压所在CSC号(当前最大支持个数63个)从1开始";
CM_ SG_ 2332295007 BAT_Ucell_Min_CELL_31 "最低单体电压所在电芯位置（当前最大位号63）从1开始";
CM_ SG_ 2332295007 BAT_Ucell_Max_31 "最高单体电压";
CM_ SG_ 2332295007 BAT_Ucell_Min_31 "最低单体电压";
CM_ SG_ 2332295008 CRC_S2A_S3_32 "S2A概要数据3 的CRC";
CM_ SG_ 2332295008 BAT_Ucell_Max_CSC_32 "最高单体电压所在CSC号(当前最大支持63个)从1开始";
CM_ SG_ 2332295008 BAT_Ucell_Max_CELL_32 "最高单体电压所在电芯位置（当前最大位号63）从1开始";
CM_ SG_ 2332295008 BAT_Ucell_Min_CSC_32 "最低单体电压所在CSC号(当前最大支持个数63个)从1开始";
CM_ SG_ 2332295008 BAT_Ucell_Min_CELL_32 "最低单体电压所在电芯位置（当前最大位号63）从1开始";
CM_ SG_ 2332295008 BAT_Ucell_Max_32 "最高单体电压";
CM_ SG_ 2332295008 BAT_Ucell_Min_32 "最低单体电压";
CM_ SG_ 2332295009 CRC_S2A_S3_33 "S2A概要数据3 的CRC";
CM_ SG_ 2332295009 BAT_Ucell_Max_CSC_33 "最高单体电压所在CSC号(当前最大支持63个)从1开始";
CM_ SG_ 2332295009 BAT_Ucell_Max_CELL_33 "最高单体电压所在电芯位置（当前最大位号63）从1开始";
CM_ SG_ 2332295009 BAT_Ucell_Min_CSC_33 "最低单体电压所在CSC号(当前最大支持个数63个)从1开始";
CM_ SG_ 2332295009 BAT_Ucell_Min_CELL_33 "最低单体电压所在电芯位置（当前最大位号63）从1开始";
CM_ SG_ 2332295009 BAT_Ucell_Max_33 "最高单体电压";
CM_ SG_ 2332295009 BAT_Ucell_Min_33 "最低单体电压";
CM_ SG_ 2332295010 CRC_S2A_S3_34 "S2A概要数据3 的CRC";
CM_ SG_ 2332295010 BAT_Ucell_Max_CSC_34 "最高单体电压所在CSC号(当前最大支持63个)从1开始";
CM_ SG_ 2332295010 BAT_Ucell_Max_CELL_34 "最高单体电压所在电芯位置（当前最大位号63）从1开始";
CM_ SG_ 2332295010 BAT_Ucell_Min_CSC_34 "最低单体电压所在CSC号(当前最大支持个数63个)从1开始";
CM_ SG_ 2332295010 BAT_Ucell_Min_CELL_34 "最低单体电压所在电芯位置（当前最大位号63）从1开始";
CM_ SG_ 2332295010 BAT_Ucell_Max_34 "最高单体电压";
CM_ SG_ 2332295010 BAT_Ucell_Min_34 "最低单体电压";
CM_ SG_ 2332295011 CRC_S2A_S3_35 "S2A概要数据3 的CRC";
CM_ SG_ 2332295011 BAT_Ucell_Max_CSC_35 "最高单体电压所在CSC号(当前最大支持63个)从1开始";
CM_ SG_ 2332295011 BAT_Ucell_Max_CELL_35 "最高单体电压所在电芯位置（当前最大位号63）从1开始";
CM_ SG_ 2332295011 BAT_Ucell_Min_CSC_35 "最低单体电压所在CSC号(当前最大支持个数63个)从1开始";
CM_ SG_ 2332295011 BAT_Ucell_Min_CELL_35 "最低单体电压所在电芯位置（当前最大位号63）从1开始";
CM_ SG_ 2332295011 BAT_Ucell_Max_35 "最高单体电压";
CM_ SG_ 2332295011 BAT_Ucell_Min_35 "最低单体电压";
CM_ SG_ 2332295012 CRC_S2A_S3_36 "S2A概要数据3 的CRC";
CM_ SG_ 2332295012 BAT_Ucell_Max_CSC_36 "最高单体电压所在CSC号(当前最大支持63个)从1开始";
CM_ SG_ 2332295012 BAT_Ucell_Max_CELL_36 "最高单体电压所在电芯位置（当前最大位号63）从1开始";
CM_ SG_ 2332295012 BAT_Ucell_Min_CSC_36 "最低单体电压所在CSC号(当前最大支持个数63个)从1开始";
CM_ SG_ 2332295012 BAT_Ucell_Min_CELL_36 "最低单体电压所在电芯位置（当前最大位号63）从1开始";
CM_ SG_ 2332295012 BAT_Ucell_Max_36 "最高单体电压";
CM_ SG_ 2332295012 BAT_Ucell_Min_36 "最低单体电压";
CM_ SG_ 2332295013 CRC_S2A_S3_37 "S2A概要数据3 的CRC";
CM_ SG_ 2332295013 BAT_Ucell_Max_CSC_37 "最高单体电压所在CSC号(当前最大支持63个)从1开始";
CM_ SG_ 2332295013 BAT_Ucell_Max_CELL_37 "最高单体电压所在电芯位置（当前最大位号63）从1开始";
CM_ SG_ 2332295013 BAT_Ucell_Min_CSC_37 "最低单体电压所在CSC号(当前最大支持个数63个)从1开始";
CM_ SG_ 2332295013 BAT_Ucell_Min_CELL_37 "最低单体电压所在电芯位置（当前最大位号63）从1开始";
CM_ SG_ 2332295013 BAT_Ucell_Max_37 "最高单体电压";
CM_ SG_ 2332295013 BAT_Ucell_Min_37 "最低单体电压";
CM_ SG_ 2332295014 CRC_S2A_S3_38 "S2A概要数据3 的CRC";
CM_ SG_ 2332295014 BAT_Ucell_Max_CSC_38 "最高单体电压所在CSC号(当前最大支持63个)从1开始";
CM_ SG_ 2332295014 BAT_Ucell_Max_CELL_38 "最高单体电压所在电芯位置（当前最大位号63）从1开始";
CM_ SG_ 2332295014 BAT_Ucell_Min_CSC_38 "最低单体电压所在CSC号(当前最大支持个数63个)从1开始";
CM_ SG_ 2332295014 BAT_Ucell_Min_CELL_38 "最低单体电压所在电芯位置（当前最大位号63）从1开始";
CM_ SG_ 2332295014 BAT_Ucell_Max_38 "最高单体电压";
CM_ SG_ 2332295014 BAT_Ucell_Min_38 "最低单体电压";
CM_ SG_ 2332295015 CRC_S2A_S3_39 "S2A概要数据3 的CRC";
CM_ SG_ 2332295015 BAT_Ucell_Max_CSC_39 "最高单体电压所在CSC号(当前最大支持63个)从1开始";
CM_ SG_ 2332295015 BAT_Ucell_Max_CELL_39 "最高单体电压所在电芯位置（当前最大位号63）从1开始";
CM_ SG_ 2332295015 BAT_Ucell_Min_CSC_39 "最低单体电压所在CSC号(当前最大支持个数63个)从1开始";
CM_ SG_ 2332295015 BAT_Ucell_Min_CELL_39 "最低单体电压所在电芯位置（当前最大位号63）从1开始";
CM_ SG_ 2332295015 BAT_Ucell_Max_39 "最高单体电压";
CM_ SG_ 2332295015 BAT_Ucell_Min_39 "最低单体电压";
CM_ SG_ 2332295016 CRC_S2A_S3_40 "S2A概要数据3 的CRC";
CM_ SG_ 2332295016 BAT_Ucell_Max_CSC_40 "最高单体电压所在CSC号(当前最大支持63个)从1开始";
CM_ SG_ 2332295016 BAT_Ucell_Max_CELL_40 "最高单体电压所在电芯位置（当前最大位号63）从1开始";
CM_ SG_ 2332295016 BAT_Ucell_Min_CSC_40 "最低单体电压所在CSC号(当前最大支持个数63个)从1开始";
CM_ SG_ 2332295016 BAT_Ucell_Min_CELL_40 "最低单体电压所在电芯位置（当前最大位号63）从1开始";
CM_ SG_ 2332295016 BAT_Ucell_Max_40 "最高单体电压";
CM_ SG_ 2332295016 BAT_Ucell_Min_40 "最低单体电压";
CM_ SG_ 2332295017 CRC_S2A_S3_41 "S2A概要数据3 的CRC";
CM_ SG_ 2332295017 BAT_Ucell_Max_CSC_41 "最高单体电压所在CSC号(当前最大支持63个)从1开始";
CM_ SG_ 2332295017 BAT_Ucell_Max_CELL_41 "最高单体电压所在电芯位置（当前最大位号63）从1开始";
CM_ SG_ 2332295017 BAT_Ucell_Min_CSC_41 "最低单体电压所在CSC号(当前最大支持个数63个)从1开始";
CM_ SG_ 2332295017 BAT_Ucell_Min_CELL_41 "最低单体电压所在电芯位置（当前最大位号63）从1开始";
CM_ SG_ 2332295017 BAT_Ucell_Max_41 "最高单体电压";
CM_ SG_ 2332295017 BAT_Ucell_Min_41 "最低单体电压";
CM_ SG_ 2332295018 CRC_S2A_S3_42 "S2A概要数据3 的CRC";
CM_ SG_ 2332295018 BAT_Ucell_Max_CSC_42 "最高单体电压所在CSC号(当前最大支持63个)从1开始";
CM_ SG_ 2332295018 BAT_Ucell_Max_CELL_42 "最高单体电压所在电芯位置（当前最大位号63）从1开始";
CM_ SG_ 2332295018 BAT_Ucell_Min_CSC_42 "最低单体电压所在CSC号(当前最大支持个数63个)从1开始";
CM_ SG_ 2332295018 BAT_Ucell_Min_CELL_42 "最低单体电压所在电芯位置（当前最大位号63）从1开始";
CM_ SG_ 2332295018 BAT_Ucell_Max_42 "最高单体电压";
CM_ SG_ 2332295018 BAT_Ucell_Min_42 "最低单体电压";
CM_ SG_ 2332295019 CRC_S2A_S3_43 "S2A概要数据3 的CRC";
CM_ SG_ 2332295019 BAT_Ucell_Max_CSC_43 "最高单体电压所在CSC号(当前最大支持63个)从1开始";
CM_ SG_ 2332295019 BAT_Ucell_Max_CELL_43 "最高单体电压所在电芯位置（当前最大位号63）从1开始";
CM_ SG_ 2332295019 BAT_Ucell_Min_CSC_43 "最低单体电压所在CSC号(当前最大支持个数63个)从1开始";
CM_ SG_ 2332295019 BAT_Ucell_Min_CELL_43 "最低单体电压所在电芯位置（当前最大位号63）从1开始";
CM_ SG_ 2332295019 BAT_Ucell_Max_43 "最高单体电压";
CM_ SG_ 2332295019 BAT_Ucell_Min_43 "最低单体电压";
CM_ SG_ 2332295020 CRC_S2A_S3_44 "S2A概要数据3 的CRC";
CM_ SG_ 2332295020 BAT_Ucell_Max_CSC_44 "最高单体电压所在CSC号(当前最大支持63个)从1开始";
CM_ SG_ 2332295020 BAT_Ucell_Max_CELL_44 "最高单体电压所在电芯位置（当前最大位号63）从1开始";
CM_ SG_ 2332295020 BAT_Ucell_Min_CSC_44 "最低单体电压所在CSC号(当前最大支持个数63个)从1开始";
CM_ SG_ 2332295020 BAT_Ucell_Min_CELL_44 "最低单体电压所在电芯位置（当前最大位号63）从1开始";
CM_ SG_ 2332295020 BAT_Ucell_Max_44 "最高单体电压";
CM_ SG_ 2332295020 BAT_Ucell_Min_44 "最低单体电压";
CM_ SG_ 2332295021 CRC_S2A_S3_45 "S2A概要数据3 的CRC";
CM_ SG_ 2332295021 BAT_Ucell_Max_CSC_45 "最高单体电压所在CSC号(当前最大支持63个)从1开始";
CM_ SG_ 2332295021 BAT_Ucell_Max_CELL_45 "最高单体电压所在电芯位置（当前最大位号63）从1开始";
CM_ SG_ 2332295021 BAT_Ucell_Min_CSC_45 "最低单体电压所在CSC号(当前最大支持个数63个)从1开始";
CM_ SG_ 2332295021 BAT_Ucell_Min_CELL_45 "最低单体电压所在电芯位置（当前最大位号63）从1开始";
CM_ SG_ 2332295021 BAT_Ucell_Max_45 "最高单体电压";
CM_ SG_ 2332295021 BAT_Ucell_Min_45 "最低单体电压";
CM_ SG_ 2332295022 CRC_S2A_S3_46 "S2A概要数据3 的CRC";
CM_ SG_ 2332295022 BAT_Ucell_Max_CSC_46 "最高单体电压所在CSC号(当前最大支持63个)从1开始";
CM_ SG_ 2332295022 BAT_Ucell_Max_CELL_46 "最高单体电压所在电芯位置（当前最大位号63）从1开始";
CM_ SG_ 2332295022 BAT_Ucell_Min_CSC_46 "最低单体电压所在CSC号(当前最大支持个数63个)从1开始";
CM_ SG_ 2332295022 BAT_Ucell_Min_CELL_46 "最低单体电压所在电芯位置（当前最大位号63）从1开始";
CM_ SG_ 2332295022 BAT_Ucell_Max_46 "最高单体电压";
CM_ SG_ 2332295022 BAT_Ucell_Min_46 "最低单体电压";
CM_ SG_ 2332295023 CRC_S2A_S3_47 "S2A概要数据3 的CRC";
CM_ SG_ 2332295023 BAT_Ucell_Max_CSC_47 "最高单体电压所在CSC号(当前最大支持63个)从1开始";
CM_ SG_ 2332295023 BAT_Ucell_Max_CELL_47 "最高单体电压所在电芯位置（当前最大位号63）从1开始";
CM_ SG_ 2332295023 BAT_Ucell_Min_CSC_47 "最低单体电压所在CSC号(当前最大支持个数63个)从1开始";
CM_ SG_ 2332295023 BAT_Ucell_Min_CELL_47 "最低单体电压所在电芯位置（当前最大位号63）从1开始";
CM_ SG_ 2332295023 BAT_Ucell_Max_47 "最高单体电压";
CM_ SG_ 2332295023 BAT_Ucell_Min_47 "最低单体电压";
CM_ SG_ 2332295024 CRC_S2A_S3_48 "S2A概要数据3 的CRC";
CM_ SG_ 2332295024 BAT_Ucell_Max_CSC_48 "最高单体电压所在CSC号(当前最大支持63个)从1开始";
CM_ SG_ 2332295024 BAT_Ucell_Max_CELL_48 "最高单体电压所在电芯位置（当前最大位号63）从1开始";
CM_ SG_ 2332295024 BAT_Ucell_Min_CSC_48 "最低单体电压所在CSC号(当前最大支持个数63个)从1开始";
CM_ SG_ 2332295024 BAT_Ucell_Min_CELL_48 "最低单体电压所在电芯位置（当前最大位号63）从1开始";
CM_ SG_ 2332295024 BAT_Ucell_Max_48 "最高单体电压";
CM_ SG_ 2332295024 BAT_Ucell_Min_48 "最低单体电压";
CM_ SG_ 2332295025 CRC_S2A_S3_49 "S2A概要数据3 的CRC";
CM_ SG_ 2332295025 BAT_Ucell_Max_CSC_49 "最高单体电压所在CSC号(当前最大支持63个)从1开始";
CM_ SG_ 2332295025 BAT_Ucell_Max_CELL_49 "最高单体电压所在电芯位置（当前最大位号63）从1开始";
CM_ SG_ 2332295025 BAT_Ucell_Min_CSC_49 "最低单体电压所在CSC号(当前最大支持个数63个)从1开始";
CM_ SG_ 2332295025 BAT_Ucell_Min_CELL_49 "最低单体电压所在电芯位置（当前最大位号63）从1开始";
CM_ SG_ 2332295025 BAT_Ucell_Max_49 "最高单体电压";
CM_ SG_ 2332295025 BAT_Ucell_Min_49 "最低单体电压";
CM_ SG_ 2332295026 CRC_S2A_S3_50 "S2A概要数据3 的CRC";
CM_ SG_ 2332295026 BAT_Ucell_Max_CSC_50 "最高单体电压所在CSC号(当前最大支持63个)从1开始";
CM_ SG_ 2332295026 BAT_Ucell_Max_CELL_50 "最高单体电压所在电芯位置（当前最大位号63）从1开始";
CM_ SG_ 2332295026 BAT_Ucell_Min_CSC_50 "最低单体电压所在CSC号(当前最大支持个数63个)从1开始";
CM_ SG_ 2332295026 BAT_Ucell_Min_CELL_50 "最低单体电压所在电芯位置（当前最大位号63）从1开始";
CM_ SG_ 2332295026 BAT_Ucell_Max_50 "最高单体电压";
CM_ SG_ 2332295026 BAT_Ucell_Min_50 "最低单体电压";
CM_ SG_ 2332295027 CRC_S2A_S3_51 "S2A概要数据3 的CRC";
CM_ SG_ 2332295027 BAT_Ucell_Max_CSC_51 "最高单体电压所在CSC号(当前最大支持63个)从1开始";
CM_ SG_ 2332295027 BAT_Ucell_Max_CELL_51 "最高单体电压所在电芯位置（当前最大位号63）从1开始";
CM_ SG_ 2332295027 BAT_Ucell_Min_CSC_51 "最低单体电压所在CSC号(当前最大支持个数63个)从1开始";
CM_ SG_ 2332295027 BAT_Ucell_Min_CELL_51 "最低单体电压所在电芯位置（当前最大位号63）从1开始";
CM_ SG_ 2332295027 BAT_Ucell_Max_51 "最高单体电压";
CM_ SG_ 2332295027 BAT_Ucell_Min_51 "最低单体电压";
CM_ SG_ 2332295028 CRC_S2A_S3_52 "S2A概要数据3 的CRC";
CM_ SG_ 2332295028 BAT_Ucell_Max_CSC_52 "最高单体电压所在CSC号(当前最大支持63个)从1开始";
CM_ SG_ 2332295028 BAT_Ucell_Max_CELL_52 "最高单体电压所在电芯位置（当前最大位号63）从1开始";
CM_ SG_ 2332295028 BAT_Ucell_Min_CSC_52 "最低单体电压所在CSC号(当前最大支持个数63个)从1开始";
CM_ SG_ 2332295028 BAT_Ucell_Min_CELL_52 "最低单体电压所在电芯位置（当前最大位号63）从1开始";
CM_ SG_ 2332295028 BAT_Ucell_Max_52 "最高单体电压";
CM_ SG_ 2332295028 BAT_Ucell_Min_52 "最低单体电压";
CM_ SG_ 2332295029 CRC_S2A_S3_53 "S2A概要数据3 的CRC";
CM_ SG_ 2332295029 BAT_Ucell_Max_CSC_53 "最高单体电压所在CSC号(当前最大支持63个)从1开始";
CM_ SG_ 2332295029 BAT_Ucell_Max_CELL_53 "最高单体电压所在电芯位置（当前最大位号63）从1开始";
CM_ SG_ 2332295029 BAT_Ucell_Min_CSC_53 "最低单体电压所在CSC号(当前最大支持个数63个)从1开始";
CM_ SG_ 2332295029 BAT_Ucell_Min_CELL_53 "最低单体电压所在电芯位置（当前最大位号63）从1开始";
CM_ SG_ 2332295029 BAT_Ucell_Max_53 "最高单体电压";
CM_ SG_ 2332295029 BAT_Ucell_Min_53 "最低单体电压";
CM_ SG_ 2332295030 CRC_S2A_S3_54 "S2A概要数据3 的CRC";
CM_ SG_ 2332295030 BAT_Ucell_Max_CSC_54 "最高单体电压所在CSC号(当前最大支持63个)从1开始";
CM_ SG_ 2332295030 BAT_Ucell_Max_CELL_54 "最高单体电压所在电芯位置（当前最大位号63）从1开始";
CM_ SG_ 2332295030 BAT_Ucell_Min_CSC_54 "最低单体电压所在CSC号(当前最大支持个数63个)从1开始";
CM_ SG_ 2332295030 BAT_Ucell_Min_CELL_54 "最低单体电压所在电芯位置（当前最大位号63）从1开始";
CM_ SG_ 2332295030 BAT_Ucell_Max_54 "最高单体电压";
CM_ SG_ 2332295030 BAT_Ucell_Min_54 "最低单体电压";
CM_ SG_ 2332295031 CRC_S2A_S3_55 "S2A概要数据3 的CRC";
CM_ SG_ 2332295031 BAT_Ucell_Max_CSC_55 "最高单体电压所在CSC号(当前最大支持63个)从1开始";
CM_ SG_ 2332295031 BAT_Ucell_Max_CELL_55 "最高单体电压所在电芯位置（当前最大位号63）从1开始";
CM_ SG_ 2332295031 BAT_Ucell_Min_CSC_55 "最低单体电压所在CSC号(当前最大支持个数63个)从1开始";
CM_ SG_ 2332295031 BAT_Ucell_Min_CELL_55 "最低单体电压所在电芯位置（当前最大位号63）从1开始";
CM_ SG_ 2332295031 BAT_Ucell_Max_55 "最高单体电压";
CM_ SG_ 2332295031 BAT_Ucell_Min_55 "最低单体电压";
CM_ SG_ 2332295032 CRC_S2A_S3_56 "S2A概要数据3 的CRC";
CM_ SG_ 2332295032 BAT_Ucell_Max_CSC_56 "最高单体电压所在CSC号(当前最大支持63个)从1开始";
CM_ SG_ 2332295032 BAT_Ucell_Max_CELL_56 "最高单体电压所在电芯位置（当前最大位号63）从1开始";
CM_ SG_ 2332295032 BAT_Ucell_Min_CSC_56 "最低单体电压所在CSC号(当前最大支持个数63个)从1开始";
CM_ SG_ 2332295032 BAT_Ucell_Min_CELL_56 "最低单体电压所在电芯位置（当前最大位号63）从1开始";
CM_ SG_ 2332295032 BAT_Ucell_Max_56 "最高单体电压";
CM_ SG_ 2332295032 BAT_Ucell_Min_56 "最低单体电压";
CM_ SG_ 2332295033 CRC_S2A_S3_57 "S2A概要数据3 的CRC";
CM_ SG_ 2332295033 BAT_Ucell_Max_CSC_57 "最高单体电压所在CSC号(当前最大支持63个)从1开始";
CM_ SG_ 2332295033 BAT_Ucell_Max_CELL_57 "最高单体电压所在电芯位置（当前最大位号63）从1开始";
CM_ SG_ 2332295033 BAT_Ucell_Min_CSC_57 "最低单体电压所在CSC号(当前最大支持个数63个)从1开始";
CM_ SG_ 2332295033 BAT_Ucell_Min_CELL_57 "最低单体电压所在电芯位置（当前最大位号63）从1开始";
CM_ SG_ 2332295033 BAT_Ucell_Max_57 "最高单体电压";
CM_ SG_ 2332295033 BAT_Ucell_Min_57 "最低单体电压";
CM_ SG_ 2332295034 CRC_S2A_S3_58 "S2A概要数据3 的CRC";
CM_ SG_ 2332295034 BAT_Ucell_Max_CSC_58 "最高单体电压所在CSC号(当前最大支持63个)从1开始";
CM_ SG_ 2332295034 BAT_Ucell_Max_CELL_58 "最高单体电压所在电芯位置（当前最大位号63）从1开始";
CM_ SG_ 2332295034 BAT_Ucell_Min_CSC_58 "最低单体电压所在CSC号(当前最大支持个数63个)从1开始";
CM_ SG_ 2332295034 BAT_Ucell_Min_CELL_58 "最低单体电压所在电芯位置（当前最大位号63）从1开始";
CM_ SG_ 2332295034 BAT_Ucell_Max_58 "最高单体电压";
CM_ SG_ 2332295034 BAT_Ucell_Min_58 "最低单体电压";
CM_ SG_ 2332295035 CRC_S2A_S3_59 "S2A概要数据3 的CRC";
CM_ SG_ 2332295035 BAT_Ucell_Max_CSC_59 "最高单体电压所在CSC号(当前最大支持63个)从1开始";
CM_ SG_ 2332295035 BAT_Ucell_Max_CELL_59 "最高单体电压所在电芯位置（当前最大位号63）从1开始";
CM_ SG_ 2332295035 BAT_Ucell_Min_CSC_59 "最低单体电压所在CSC号(当前最大支持个数63个)从1开始";
CM_ SG_ 2332295035 BAT_Ucell_Min_CELL_59 "最低单体电压所在电芯位置（当前最大位号63）从1开始";
CM_ SG_ 2332295035 BAT_Ucell_Max_59 "最高单体电压";
CM_ SG_ 2332295035 BAT_Ucell_Min_59 "最低单体电压";
CM_ SG_ 2332295036 CRC_S2A_S3_60 "S2A概要数据3 的CRC";
CM_ SG_ 2332295036 BAT_Ucell_Max_CSC_60 "最高单体电压所在CSC号(当前最大支持63个)从1开始";
CM_ SG_ 2332295036 BAT_Ucell_Max_CELL_60 "最高单体电压所在电芯位置（当前最大位号63）从1开始";
CM_ SG_ 2332295036 BAT_Ucell_Min_CSC_60 "最低单体电压所在CSC号(当前最大支持个数63个)从1开始";
CM_ SG_ 2332295036 BAT_Ucell_Min_CELL_60 "最低单体电压所在电芯位置（当前最大位号63）从1开始";
CM_ SG_ 2332295036 BAT_Ucell_Max_60 "最高单体电压";
CM_ SG_ 2332295036 BAT_Ucell_Min_60 "最低单体电压";
CM_ SG_ 2332295037 CRC_S2A_S3_61 "S2A概要数据3 的CRC";
CM_ SG_ 2332295037 BAT_Ucell_Max_CSC_61 "最高单体电压所在CSC号(当前最大支持63个)从1开始";
CM_ SG_ 2332295037 BAT_Ucell_Max_CELL_61 "最高单体电压所在电芯位置（当前最大位号63）从1开始";
CM_ SG_ 2332295037 BAT_Ucell_Min_CSC_61 "最低单体电压所在CSC号(当前最大支持个数63个)从1开始";
CM_ SG_ 2332295037 BAT_Ucell_Min_CELL_61 "最低单体电压所在电芯位置（当前最大位号63）从1开始";
CM_ SG_ 2332295037 BAT_Ucell_Max_61 "最高单体电压";
CM_ SG_ 2332295037 BAT_Ucell_Min_61 "最低单体电压";
CM_ SG_ 2332295038 CRC_S2A_S3_62 "S2A概要数据3 的CRC";
CM_ SG_ 2332295038 BAT_Ucell_Max_CSC_62 "最高单体电压所在CSC号(当前最大支持63个)从1开始";
CM_ SG_ 2332295038 BAT_Ucell_Max_CELL_62 "最高单体电压所在电芯位置（当前最大位号63）从1开始";
CM_ SG_ 2332295038 BAT_Ucell_Min_CSC_62 "最低单体电压所在CSC号(当前最大支持个数63个)从1开始";
CM_ SG_ 2332295038 BAT_Ucell_Min_CELL_62 "最低单体电压所在电芯位置（当前最大位号63）从1开始";
CM_ SG_ 2332295038 BAT_Ucell_Max_62 "最高单体电压";
CM_ SG_ 2332295038 BAT_Ucell_Min_62 "最低单体电压";
CM_ SG_ 2332295039 CRC_S2A_S3_63 "S2A概要数据3 的CRC";
CM_ SG_ 2332295039 BAT_Ucell_Max_CSC_63 "最高单体电压所在CSC号(当前最大支持63个)从1开始";
CM_ SG_ 2332295039 BAT_Ucell_Max_CELL_63 "最高单体电压所在电芯位置（当前最大位号63）从1开始";
CM_ SG_ 2332295039 BAT_Ucell_Min_CSC_63 "最低单体电压所在CSC号(当前最大支持个数63个)从1开始";
CM_ SG_ 2332295039 BAT_Ucell_Min_CELL_63 "最低单体电压所在电芯位置（当前最大位号63）从1开始";
CM_ SG_ 2332295039 BAT_Ucell_Max_63 "最高单体电压";
CM_ SG_ 2332295039 BAT_Ucell_Min_63 "最低单体电压";
CM_ SG_ 2332360513 CRC_S2A_S4_01 "S2A概要数据4 的CRC";
CM_ SG_ 2332360513 BAT_Ucell_Avg_01 "平均单体电压";
CM_ SG_ 2332360513 BAT_T_Max_01 "最高单体温度";
CM_ SG_ 2332360513 BAT_T_Min_01 "最低单体温度";
CM_ SG_ 2332360513 BAT_T_Avg_01 "平均单体温度";
CM_ SG_ 2332360513 BAT_T_Max_CSC_01 "最高温度所在CSC号";
CM_ SG_ 2332360513 BAT_T_Min_CSC_01 "最低温度所在CSC号";
CM_ SG_ 2332360514 CRC_S2A_S4_02 "S2A概要数据4 的CRC";
CM_ SG_ 2332360514 BAT_Ucell_Avg_02 "平均单体电压";
CM_ SG_ 2332360514 BAT_T_Max_02 "最高单体温度";
CM_ SG_ 2332360514 BAT_T_Min_02 "最低单体温度";
CM_ SG_ 2332360514 BAT_T_Avg_02 "平均单体温度";
CM_ SG_ 2332360514 BAT_T_Max_CSC_02 "最高温度所在CSC号";
CM_ SG_ 2332360514 BAT_T_Min_CSC_02 "最低温度所在CSC号";
CM_ SG_ 2332360515 CRC_S2A_S4_03 "S2A概要数据4 的CRC";
CM_ SG_ 2332360515 BAT_Ucell_Avg_03 "平均单体电压";
CM_ SG_ 2332360515 BAT_T_Max_03 "最高单体温度";
CM_ SG_ 2332360515 BAT_T_Min_03 "最低单体温度";
CM_ SG_ 2332360515 BAT_T_Avg_03 "平均单体温度";
CM_ SG_ 2332360515 BAT_T_Max_CSC_03 "最高温度所在CSC号";
CM_ SG_ 2332360515 BAT_T_Min_CSC_03 "最低温度所在CSC号";
CM_ SG_ 2332360516 CRC_S2A_S4_04 "S2A概要数据4 的CRC";
CM_ SG_ 2332360516 BAT_Ucell_Avg_04 "平均单体电压";
CM_ SG_ 2332360516 BAT_T_Max_04 "最高单体温度";
CM_ SG_ 2332360516 BAT_T_Min_04 "最低单体温度";
CM_ SG_ 2332360516 BAT_T_Avg_04 "平均单体温度";
CM_ SG_ 2332360516 BAT_T_Max_CSC_04 "最高温度所在CSC号";
CM_ SG_ 2332360516 BAT_T_Min_CSC_04 "最低温度所在CSC号";
CM_ SG_ 2332360517 CRC_S2A_S4_05 "S2A概要数据4 的CRC";
CM_ SG_ 2332360517 BAT_Ucell_Avg_05 "平均单体电压";
CM_ SG_ 2332360517 BAT_T_Max_05 "最高单体温度";
CM_ SG_ 2332360517 BAT_T_Min_05 "最低单体温度";
CM_ SG_ 2332360517 BAT_T_Avg_05 "平均单体温度";
CM_ SG_ 2332360517 BAT_T_Max_CSC_05 "最高温度所在CSC号";
CM_ SG_ 2332360517 BAT_T_Min_CSC_05 "最低温度所在CSC号";
CM_ SG_ 2332360518 CRC_S2A_S4_06 "S2A概要数据4 的CRC";
CM_ SG_ 2332360518 BAT_Ucell_Avg_06 "平均单体电压";
CM_ SG_ 2332360518 BAT_T_Max_06 "最高单体温度";
CM_ SG_ 2332360518 BAT_T_Min_06 "最低单体温度";
CM_ SG_ 2332360518 BAT_T_Avg_06 "平均单体温度";
CM_ SG_ 2332360518 BAT_T_Max_CSC_06 "最高温度所在CSC号";
CM_ SG_ 2332360518 BAT_T_Min_CSC_06 "最低温度所在CSC号";
CM_ SG_ 2332360519 CRC_S2A_S4_07 "S2A概要数据4 的CRC";
CM_ SG_ 2332360519 BAT_Ucell_Avg_07 "平均单体电压";
CM_ SG_ 2332360519 BAT_T_Max_07 "最高单体温度";
CM_ SG_ 2332360519 BAT_T_Min_07 "最低单体温度";
CM_ SG_ 2332360519 BAT_T_Avg_07 "平均单体温度";
CM_ SG_ 2332360519 BAT_T_Max_CSC_07 "最高温度所在CSC号";
CM_ SG_ 2332360519 BAT_T_Min_CSC_07 "最低温度所在CSC号";
CM_ SG_ 2332360520 CRC_S2A_S4_08 "S2A概要数据4 的CRC";
CM_ SG_ 2332360520 BAT_Ucell_Avg_08 "平均单体电压";
CM_ SG_ 2332360520 BAT_T_Max_08 "最高单体温度";
CM_ SG_ 2332360520 BAT_T_Min_08 "最低单体温度";
CM_ SG_ 2332360520 BAT_T_Avg_08 "平均单体温度";
CM_ SG_ 2332360520 BAT_T_Max_CSC_08 "最高温度所在CSC号";
CM_ SG_ 2332360520 BAT_T_Min_CSC_08 "最低温度所在CSC号";
CM_ SG_ 2332360521 CRC_S2A_S4_09 "S2A概要数据4 的CRC";
CM_ SG_ 2332360521 BAT_Ucell_Avg_09 "平均单体电压";
CM_ SG_ 2332360521 BAT_T_Max_09 "最高单体温度";
CM_ SG_ 2332360521 BAT_T_Min_09 "最低单体温度";
CM_ SG_ 2332360521 BAT_T_Avg_09 "平均单体温度";
CM_ SG_ 2332360521 BAT_T_Max_CSC_09 "最高温度所在CSC号";
CM_ SG_ 2332360521 BAT_T_Min_CSC_09 "最低温度所在CSC号";
CM_ SG_ 2332360522 CRC_S2A_S4_10 "S2A概要数据4 的CRC";
CM_ SG_ 2332360522 BAT_Ucell_Avg_10 "平均单体电压";
CM_ SG_ 2332360522 BAT_T_Max_10 "最高单体温度";
CM_ SG_ 2332360522 BAT_T_Min_10 "最低单体温度";
CM_ SG_ 2332360522 BAT_T_Avg_10 "平均单体温度";
CM_ SG_ 2332360522 BAT_T_Max_CSC_10 "最高温度所在CSC号";
CM_ SG_ 2332360522 BAT_T_Min_CSC_10 "最低温度所在CSC号";
CM_ SG_ 2332360523 CRC_S2A_S4_11 "S2A概要数据4 的CRC";
CM_ SG_ 2332360523 BAT_Ucell_Avg_11 "平均单体电压";
CM_ SG_ 2332360523 BAT_T_Max_11 "最高单体温度";
CM_ SG_ 2332360523 BAT_T_Min_11 "最低单体温度";
CM_ SG_ 2332360523 BAT_T_Avg_11 "平均单体温度";
CM_ SG_ 2332360523 BAT_T_Max_CSC_11 "最高温度所在CSC号";
CM_ SG_ 2332360523 BAT_T_Min_CSC_11 "最低温度所在CSC号";
CM_ SG_ 2332360524 CRC_S2A_S4_12 "S2A概要数据4 的CRC";
CM_ SG_ 2332360524 BAT_Ucell_Avg_12 "平均单体电压";
CM_ SG_ 2332360524 BAT_T_Max_12 "最高单体温度";
CM_ SG_ 2332360524 BAT_T_Min_12 "最低单体温度";
CM_ SG_ 2332360524 BAT_T_Avg_12 "平均单体温度";
CM_ SG_ 2332360524 BAT_T_Max_CSC_12 "最高温度所在CSC号";
CM_ SG_ 2332360524 BAT_T_Min_CSC_12 "最低温度所在CSC号";
CM_ SG_ 2332360525 CRC_S2A_S4_13 "S2A概要数据4 的CRC";
CM_ SG_ 2332360525 BAT_Ucell_Avg_13 "平均单体电压";
CM_ SG_ 2332360525 BAT_T_Max_13 "最高单体温度";
CM_ SG_ 2332360525 BAT_T_Min_13 "最低单体温度";
CM_ SG_ 2332360525 BAT_T_Avg_13 "平均单体温度";
CM_ SG_ 2332360525 BAT_T_Max_CSC_13 "最高温度所在CSC号";
CM_ SG_ 2332360525 BAT_T_Min_CSC_13 "最低温度所在CSC号";
CM_ SG_ 2332360526 CRC_S2A_S4_14 "S2A概要数据4 的CRC";
CM_ SG_ 2332360526 BAT_Ucell_Avg_14 "平均单体电压";
CM_ SG_ 2332360526 BAT_T_Max_14 "最高单体温度";
CM_ SG_ 2332360526 BAT_T_Min_14 "最低单体温度";
CM_ SG_ 2332360526 BAT_T_Avg_14 "平均单体温度";
CM_ SG_ 2332360526 BAT_T_Max_CSC_14 "最高温度所在CSC号";
CM_ SG_ 2332360526 BAT_T_Min_CSC_14 "最低温度所在CSC号";
CM_ SG_ 2332360527 CRC_S2A_S4_15 "S2A概要数据4 的CRC";
CM_ SG_ 2332360527 BAT_Ucell_Avg_15 "平均单体电压";
CM_ SG_ 2332360527 BAT_T_Max_15 "最高单体温度";
CM_ SG_ 2332360527 BAT_T_Min_15 "最低单体温度";
CM_ SG_ 2332360527 BAT_T_Avg_15 "平均单体温度";
CM_ SG_ 2332360527 BAT_T_Max_CSC_15 "最高温度所在CSC号";
CM_ SG_ 2332360527 BAT_T_Min_CSC_15 "最低温度所在CSC号";
CM_ SG_ 2332360528 CRC_S2A_S4_16 "S2A概要数据4 的CRC";
CM_ SG_ 2332360528 BAT_Ucell_Avg_16 "平均单体电压";
CM_ SG_ 2332360528 BAT_T_Max_16 "最高单体温度";
CM_ SG_ 2332360528 BAT_T_Min_16 "最低单体温度";
CM_ SG_ 2332360528 BAT_T_Avg_16 "平均单体温度";
CM_ SG_ 2332360528 BAT_T_Max_CSC_16 "最高温度所在CSC号";
CM_ SG_ 2332360528 BAT_T_Min_CSC_16 "最低温度所在CSC号";
CM_ SG_ 2332360529 CRC_S2A_S4_17 "S2A概要数据4 的CRC";
CM_ SG_ 2332360529 BAT_Ucell_Avg_17 "平均单体电压";
CM_ SG_ 2332360529 BAT_T_Max_17 "最高单体温度";
CM_ SG_ 2332360529 BAT_T_Min_17 "最低单体温度";
CM_ SG_ 2332360529 BAT_T_Avg_17 "平均单体温度";
CM_ SG_ 2332360529 BAT_T_Max_CSC_17 "最高温度所在CSC号";
CM_ SG_ 2332360529 BAT_T_Min_CSC_17 "最低温度所在CSC号";
CM_ SG_ 2332360530 CRC_S2A_S4_18 "S2A概要数据4 的CRC";
CM_ SG_ 2332360530 BAT_Ucell_Avg_18 "平均单体电压";
CM_ SG_ 2332360530 BAT_T_Max_18 "最高单体温度";
CM_ SG_ 2332360530 BAT_T_Min_18 "最低单体温度";
CM_ SG_ 2332360530 BAT_T_Avg_18 "平均单体温度";
CM_ SG_ 2332360530 BAT_T_Max_CSC_18 "最高温度所在CSC号";
CM_ SG_ 2332360530 BAT_T_Min_CSC_18 "最低温度所在CSC号";
CM_ SG_ 2332360531 CRC_S2A_S4_19 "S2A概要数据4 的CRC";
CM_ SG_ 2332360531 BAT_Ucell_Avg_19 "平均单体电压";
CM_ SG_ 2332360531 BAT_T_Max_19 "最高单体温度";
CM_ SG_ 2332360531 BAT_T_Min_19 "最低单体温度";
CM_ SG_ 2332360531 BAT_T_Avg_19 "平均单体温度";
CM_ SG_ 2332360531 BAT_T_Max_CSC_19 "最高温度所在CSC号";
CM_ SG_ 2332360531 BAT_T_Min_CSC_19 "最低温度所在CSC号";
CM_ SG_ 2332360532 CRC_S2A_S4_20 "S2A概要数据4 的CRC";
CM_ SG_ 2332360532 BAT_Ucell_Avg_20 "平均单体电压";
CM_ SG_ 2332360532 BAT_T_Max_20 "最高单体温度";
CM_ SG_ 2332360532 BAT_T_Min_20 "最低单体温度";
CM_ SG_ 2332360532 BAT_T_Avg_20 "平均单体温度";
CM_ SG_ 2332360532 BAT_T_Max_CSC_20 "最高温度所在CSC号";
CM_ SG_ 2332360532 BAT_T_Min_CSC_20 "最低温度所在CSC号";
CM_ SG_ 2332360533 CRC_S2A_S4_21 "S2A概要数据4 的CRC";
CM_ SG_ 2332360533 BAT_Ucell_Avg_21 "平均单体电压";
CM_ SG_ 2332360533 BAT_T_Max_21 "最高单体温度";
CM_ SG_ 2332360533 BAT_T_Min_21 "最低单体温度";
CM_ SG_ 2332360533 BAT_T_Avg_21 "平均单体温度";
CM_ SG_ 2332360533 BAT_T_Max_CSC_21 "最高温度所在CSC号";
CM_ SG_ 2332360533 BAT_T_Min_CSC_21 "最低温度所在CSC号";
CM_ SG_ 2332360534 CRC_S2A_S4_22 "S2A概要数据4 的CRC";
CM_ SG_ 2332360534 BAT_Ucell_Avg_22 "平均单体电压";
CM_ SG_ 2332360534 BAT_T_Max_22 "最高单体温度";
CM_ SG_ 2332360534 BAT_T_Min_22 "最低单体温度";
CM_ SG_ 2332360534 BAT_T_Avg_22 "平均单体温度";
CM_ SG_ 2332360534 BAT_T_Max_CSC_22 "最高温度所在CSC号";
CM_ SG_ 2332360534 BAT_T_Min_CSC_22 "最低温度所在CSC号";
CM_ SG_ 2332360535 CRC_S2A_S4_23 "S2A概要数据4 的CRC";
CM_ SG_ 2332360535 BAT_Ucell_Avg_23 "平均单体电压";
CM_ SG_ 2332360535 BAT_T_Max_23 "最高单体温度";
CM_ SG_ 2332360535 BAT_T_Min_23 "最低单体温度";
CM_ SG_ 2332360535 BAT_T_Avg_23 "平均单体温度";
CM_ SG_ 2332360535 BAT_T_Max_CSC_23 "最高温度所在CSC号";
CM_ SG_ 2332360535 BAT_T_Min_CSC_23 "最低温度所在CSC号";
CM_ SG_ 2332360536 CRC_S2A_S4_24 "S2A概要数据4 的CRC";
CM_ SG_ 2332360536 BAT_Ucell_Avg_24 "平均单体电压";
CM_ SG_ 2332360536 BAT_T_Max_24 "最高单体温度";
CM_ SG_ 2332360536 BAT_T_Min_24 "最低单体温度";
CM_ SG_ 2332360536 BAT_T_Avg_24 "平均单体温度";
CM_ SG_ 2332360536 BAT_T_Max_CSC_24 "最高温度所在CSC号";
CM_ SG_ 2332360536 BAT_T_Min_CSC_24 "最低温度所在CSC号";
CM_ SG_ 2332360537 CRC_S2A_S4_25 "S2A概要数据4 的CRC";
CM_ SG_ 2332360537 BAT_Ucell_Avg_25 "平均单体电压";
CM_ SG_ 2332360537 BAT_T_Max_25 "最高单体温度";
CM_ SG_ 2332360537 BAT_T_Min_25 "最低单体温度";
CM_ SG_ 2332360537 BAT_T_Avg_25 "平均单体温度";
CM_ SG_ 2332360537 BAT_T_Max_CSC_25 "最高温度所在CSC号";
CM_ SG_ 2332360537 BAT_T_Min_CSC_25 "最低温度所在CSC号";
CM_ SG_ 2332360538 CRC_S2A_S4_26 "S2A概要数据4 的CRC";
CM_ SG_ 2332360538 BAT_Ucell_Avg_26 "平均单体电压";
CM_ SG_ 2332360538 BAT_T_Max_26 "最高单体温度";
CM_ SG_ 2332360538 BAT_T_Min_26 "最低单体温度";
CM_ SG_ 2332360538 BAT_T_Avg_26 "平均单体温度";
CM_ SG_ 2332360538 BAT_T_Max_CSC_26 "最高温度所在CSC号";
CM_ SG_ 2332360538 BAT_T_Min_CSC_26 "最低温度所在CSC号";
CM_ SG_ 2332360539 CRC_S2A_S4_27 "S2A概要数据4 的CRC";
CM_ SG_ 2332360539 BAT_Ucell_Avg_27 "平均单体电压";
CM_ SG_ 2332360539 BAT_T_Max_27 "最高单体温度";
CM_ SG_ 2332360539 BAT_T_Min_27 "最低单体温度";
CM_ SG_ 2332360539 BAT_T_Avg_27 "平均单体温度";
CM_ SG_ 2332360539 BAT_T_Max_CSC_27 "最高温度所在CSC号";
CM_ SG_ 2332360539 BAT_T_Min_CSC_27 "最低温度所在CSC号";
CM_ SG_ 2332360540 CRC_S2A_S4_28 "S2A概要数据4 的CRC";
CM_ SG_ 2332360540 BAT_Ucell_Avg_28 "平均单体电压";
CM_ SG_ 2332360540 BAT_T_Max_28 "最高单体温度";
CM_ SG_ 2332360540 BAT_T_Min_28 "最低单体温度";
CM_ SG_ 2332360540 BAT_T_Avg_28 "平均单体温度";
CM_ SG_ 2332360540 BAT_T_Max_CSC_28 "最高温度所在CSC号";
CM_ SG_ 2332360540 BAT_T_Min_CSC_28 "最低温度所在CSC号";
CM_ SG_ 2332360541 CRC_S2A_S4_29 "S2A概要数据4 的CRC";
CM_ SG_ 2332360541 BAT_Ucell_Avg_29 "平均单体电压";
CM_ SG_ 2332360541 BAT_T_Max_29 "最高单体温度";
CM_ SG_ 2332360541 BAT_T_Min_29 "最低单体温度";
CM_ SG_ 2332360541 BAT_T_Avg_29 "平均单体温度";
CM_ SG_ 2332360541 BAT_T_Max_CSC_29 "最高温度所在CSC号";
CM_ SG_ 2332360541 BAT_T_Min_CSC_29 "最低温度所在CSC号";
CM_ SG_ 2332360542 CRC_S2A_S4_30 "S2A概要数据4 的CRC";
CM_ SG_ 2332360542 BAT_Ucell_Avg_30 "平均单体电压";
CM_ SG_ 2332360542 BAT_T_Max_30 "最高单体温度";
CM_ SG_ 2332360542 BAT_T_Min_30 "最低单体温度";
CM_ SG_ 2332360542 BAT_T_Avg_30 "平均单体温度";
CM_ SG_ 2332360542 BAT_T_Max_CSC_30 "最高温度所在CSC号";
CM_ SG_ 2332360542 BAT_T_Min_CSC_30 "最低温度所在CSC号";
VAL_ 2332229470 S2A_S2_FullChgFlgFromSBMU_30 0 "未置位满充" 85 "置位满充" ;
VAL_ 2332229471 S2A_S2_FullChgFlgFromSBMU_31 0 "未置位满充" 85 "置位满充" ;
VAL_ 2332229472 S2A_S2_FullChgFlgFromSBMU_32 0 "未置位满充" 85 "置位满充" ;
VAL_ 2332229473 S2A_S2_FullChgFlgFromSBMU_33 0 "未置位满充" 85 "置位满充" ;
VAL_ 2332229474 S2A_S2_FullChgFlgFromSBMU_34 0 "未置位满充" 85 "置位满充" ;
VAL_ 2332229475 S2A_S2_FullChgFlgFromSBMU_35 0 "未置位满充" 85 "置位满充" ;
VAL_ 2332229476 S2A_S2_FullChgFlgFromSBMU_36 0 "未置位满充" 85 "置位满充" ;
VAL_ 2332229477 S2A_S2_FullChgFlgFromSBMU_37 0 "未置位满充" 85 "置位满充" ;
VAL_ 2332229478 S2A_S2_FullChgFlgFromSBMU_38 0 "未置位满充" 85 "置位满充" ;
VAL_ 2332229479 S2A_S2_FullChgFlgFromSBMU_39 0 "未置位满充" 85 "置位满充" ;
VAL_ 2332229480 S2A_S2_FullChgFlgFromSBMU_40 0 "未置位满充" 85 "置位满充" ;
VAL_ 2332229481 S2A_S2_FullChgFlgFromSBMU_41 0 "未置位满充" 85 "置位满充" ;
VAL_ 2332229482 S2A_S2_FullChgFlgFromSBMU_42 0 "未置位满充" 85 "置位满充" ;
VAL_ 2332229483 S2A_S2_FullChgFlgFromSBMU_43 0 "未置位满充" 85 "置位满充" ;
VAL_ 2332229484 S2A_S2_FullChgFlgFromSBMU_44 0 "未置位满充" 85 "置位满充" ;
VAL_ 2332229485 S2A_S2_FullChgFlgFromSBMU_45 0 "未置位满充" 85 "置位满充" ;
VAL_ 2332229486 S2A_S2_FullChgFlgFromSBMU_46 0 "未置位满充" 85 "置位满充" ;
VAL_ 2332229487 S2A_S2_FullChgFlgFromSBMU_47 0 "未置位满充" 85 "置位满充" ;
VAL_ 2332229488 S2A_S2_FullChgFlgFromSBMU_48 0 "未置位满充" 85 "置位满充" ;
VAL_ 2332229489 S2A_S2_FullChgFlgFromSBMU_49 0 "未置位满充" 85 "置位满充" ;
VAL_ 2332229490 S2A_S2_FullChgFlgFromSBMU_50 0 "未置位满充" 85 "置位满充" ;
VAL_ 2332229491 S2A_S2_FullChgFlgFromSBMU_51 0 "未置位满充" 85 "置位满充" ;
VAL_ 2332229492 S2A_S2_FullChgFlgFromSBMU_52 0 "未置位满充" 85 "置位满充" ;
VAL_ 2332229493 S2A_S2_FullChgFlgFromSBMU_53 0 "未置位满充" 85 "置位满充" ;
VAL_ 2332229494 S2A_S2_FullChgFlgFromSBMU_54 0 "未置位满充" 85 "置位满充" ;
VAL_ 2332229495 S2A_S2_FullChgFlgFromSBMU_55 0 "未置位满充" 85 "置位满充" ;
VAL_ 2332229496 S2A_S2_FullChgFlgFromSBMU_56 0 "未置位满充" 85 "置位满充" ;
VAL_ 2332229497 S2A_S2_FullChgFlgFromSBMU_57 0 "未置位满充" 85 "置位满充" ;
VAL_ 2332229498 S2A_S2_FullChgFlgFromSBMU_58 0 "未置位满充" 85 "置位满充" ;
VAL_ 2332229499 S2A_S2_FullChgFlgFromSBMU_59 0 "未置位满充" 85 "置位满充" ;
VAL_ 2332229500 S2A_S2_FullChgFlgFromSBMU_60 0 "未置位满充" 85 "置位满充" ;
VAL_ 2332229501 S2A_S2_FullChgFlgFromSBMU_61 0 "未置位满充" 85 "置位满充" ;
VAL_ 2332229502 S2A_S2_FullChgFlgFromSBMU_62 0 "未置位满充" 85 "置位满充" ;
VAL_ 2332229503 S2A_S2_FullChgFlgFromSBMU_63 0 "未置位满充" 85 "置位满充" ;
VERSION ""

NS_ :

BS_:

BU_: MBMU PC SBMU IMM ETH DCDC LEMS

BO_ 2332360543 S2A_SUMDATA4__31: 8 SBMU
 SG_ CRC_S2A_S4_31 : 0|8@1+ (1,0) [0|255] ""  MBMU,PC
 SG_ BAT_Ucell_Avg_31 : 8|16@1+ (1,0) [0|65535] "mV"  MBMU,PC
 SG_ BAT_T_Max_31 : 24|8@1+ (1,-50) [-50|205] "℃"  MBMU,PC
 SG_ BAT_T_Min_31 : 32|8@1+ (1,-50) [-50|205] "℃"  MBMU,PC
 SG_ BAT_T_Avg_31 : 40|8@1+ (1,-50) [-50|205] "℃"  MBMU,PC
 SG_ BAT_T_Max_CSC_31 : 48|8@1+ (1,0) [0|255] ""  MBMU,PC
 SG_ BAT_T_Min_CSC_31 : 56|8@1+ (1,0) [0|255] ""  MBMU,PC

BO_ 2332360544 S2A_SUMDATA4__32: 8 SBMU
 SG_ CRC_S2A_S4_32 : 0|8@1+ (1,0) [0|255] ""  MBMU,PC
 SG_ BAT_Ucell_Avg_32 : 8|16@1+ (1,0) [0|65535] "mV"  MBMU,PC
 SG_ BAT_T_Max_32 : 24|8@1+ (1,-50) [-50|205] "℃"  MBMU,PC
 SG_ BAT_T_Min_32 : 32|8@1+ (1,-50) [-50|205] "℃"  MBMU,PC
 SG_ BAT_T_Avg_32 : 40|8@1+ (1,-50) [-50|205] "℃"  MBMU,PC
 SG_ BAT_T_Max_CSC_32 : 48|8@1+ (1,0) [0|255] ""  MBMU,PC
 SG_ BAT_T_Min_CSC_32 : 56|8@1+ (1,0) [0|255] ""  MBMU,PC

BO_ 2332360545 S2A_SUMDATA4__33: 8 SBMU
 SG_ CRC_S2A_S4_33 : 0|8@1+ (1,0) [0|255] ""  MBMU,PC
 SG_ BAT_Ucell_Avg_33 : 8|16@1+ (1,0) [0|65535] "mV"  MBMU,PC
 SG_ BAT_T_Max_33 : 24|8@1+ (1,-50) [-50|205] "℃"  MBMU,PC
 SG_ BAT_T_Min_33 : 32|8@1+ (1,-50) [-50|205] "℃"  MBMU,PC
 SG_ BAT_T_Avg_33 : 40|8@1+ (1,-50) [-50|205] "℃"  MBMU,PC
 SG_ BAT_T_Max_CSC_33 : 48|8@1+ (1,0) [0|255] ""  MBMU,PC
 SG_ BAT_T_Min_CSC_33 : 56|8@1+ (1,0) [0|255] ""  MBMU,PC

BO_ 2332360546 S2A_SUMDATA4__34: 8 SBMU
 SG_ CRC_S2A_S4_34 : 0|8@1+ (1,0) [0|255] ""  MBMU,PC
 SG_ BAT_Ucell_Avg_34 : 8|16@1+ (1,0) [0|65535] "mV"  MBMU,PC
 SG_ BAT_T_Max_34 : 24|8@1+ (1,-50) [-50|205] "℃"  MBMU,PC
 SG_ BAT_T_Min_34 : 32|8@1+ (1,-50) [-50|205] "℃"  MBMU,PC
 SG_ BAT_T_Avg_34 : 40|8@1+ (1,-50) [-50|205] "℃"  MBMU,PC
 SG_ BAT_T_Max_CSC_34 : 48|8@1+ (1,0) [0|255] ""  MBMU,PC
 SG_ BAT_T_Min_CSC_34 : 56|8@1+ (1,0) [0|255] ""  MBMU,PC

BO_ 2332360547 S2A_SUMDATA4__35: 8 SBMU
 SG_ CRC_S2A_S4_35 : 0|8@1+ (1,0) [0|255] ""  MBMU,PC
 SG_ BAT_Ucell_Avg_35 : 8|16@1+ (1,0) [0|65535] "mV"  MBMU,PC
 SG_ BAT_T_Max_35 : 24|8@1+ (1,-50) [-50|205] "℃"  MBMU,PC
 SG_ BAT_T_Min_35 : 32|8@1+ (1,-50) [-50|205] "℃"  MBMU,PC
 SG_ BAT_T_Avg_35 : 40|8@1+ (1,-50) [-50|205] "℃"  MBMU,PC
 SG_ BAT_T_Max_CSC_35 : 48|8@1+ (1,0) [0|255] ""  MBMU,PC
 SG_ BAT_T_Min_CSC_35 : 56|8@1+ (1,0) [0|255] ""  MBMU,PC

BO_ 2332360548 S2A_SUMDATA4__36: 8 SBMU
 SG_ CRC_S2A_S4_36 : 0|8@1+ (1,0) [0|255] ""  MBMU,PC
 SG_ BAT_Ucell_Avg_36 : 8|16@1+ (1,0) [0|65535] "mV"  MBMU,PC
 SG_ BAT_T_Max_36 : 24|8@1+ (1,-50) [-50|205] "℃"  MBMU,PC
 SG_ BAT_T_Min_36 : 32|8@1+ (1,-50) [-50|205] "℃"  MBMU,PC
 SG_ BAT_T_Avg_36 : 40|8@1+ (1,-50) [-50|205] "℃"  MBMU,PC
 SG_ BAT_T_Max_CSC_36 : 48|8@1+ (1,0) [0|255] ""  MBMU,PC
 SG_ BAT_T_Min_CSC_36 : 56|8@1+ (1,0) [0|255] ""  MBMU,PC

BO_ 2332360549 S2A_SUMDATA4__37: 8 SBMU
 SG_ CRC_S2A_S4_37 : 0|8@1+ (1,0) [0|255] ""  MBMU,PC
 SG_ BAT_Ucell_Avg_37 : 8|16@1+ (1,0) [0|65535] "mV"  MBMU,PC
 SG_ BAT_T_Max_37 : 24|8@1+ (1,-50) [-50|205] "℃"  MBMU,PC
 SG_ BAT_T_Min_37 : 32|8@1+ (1,-50) [-50|205] "℃"  MBMU,PC
 SG_ BAT_T_Avg_37 : 40|8@1+ (1,-50) [-50|205] "℃"  MBMU,PC
 SG_ BAT_T_Max_CSC_37 : 48|8@1+ (1,0) [0|255] ""  MBMU,PC
 SG_ BAT_T_Min_CSC_37 : 56|8@1+ (1,0) [0|255] ""  MBMU,PC

BO_ 2332360550 S2A_SUMDATA4__38: 8 SBMU
 SG_ CRC_S2A_S4_38 : 0|8@1+ (1,0) [0|255] ""  MBMU,PC
 SG_ BAT_Ucell_Avg_38 : 8|16@1+ (1,0) [0|65535] "mV"  MBMU,PC
 SG_ BAT_T_Max_38 : 24|8@1+ (1,-50) [-50|205] "℃"  MBMU,PC
 SG_ BAT_T_Min_38 : 32|8@1+ (1,-50) [-50|205] "℃"  MBMU,PC
 SG_ BAT_T_Avg_38 : 40|8@1+ (1,-50) [-50|205] "℃"  MBMU,PC
 SG_ BAT_T_Max_CSC_38 : 48|8@1+ (1,0) [0|255] ""  MBMU,PC
 SG_ BAT_T_Min_CSC_38 : 56|8@1+ (1,0) [0|255] ""  MBMU,PC

BO_ 2332360551 S2A_SUMDATA4__39: 8 SBMU
 SG_ CRC_S2A_S4_39 : 0|8@1+ (1,0) [0|255] ""  MBMU,PC
 SG_ BAT_Ucell_Avg_39 : 8|16@1+ (1,0) [0|65535] "mV"  MBMU,PC
 SG_ BAT_T_Max_39 : 24|8@1+ (1,-50) [-50|205] "℃"  MBMU,PC
 SG_ BAT_T_Min_39 : 32|8@1+ (1,-50) [-50|205] "℃"  MBMU,PC
 SG_ BAT_T_Avg_39 : 40|8@1+ (1,-50) [-50|205] "℃"  MBMU,PC
 SG_ BAT_T_Max_CSC_39 : 48|8@1+ (1,0) [0|255] ""  MBMU,PC
 SG_ BAT_T_Min_CSC_39 : 56|8@1+ (1,0) [0|255] ""  MBMU,PC

BO_ 2332360552 S2A_SUMDATA4__40: 8 SBMU
 SG_ CRC_S2A_S4_40 : 0|8@1+ (1,0) [0|255] ""  MBMU,PC
 SG_ BAT_Ucell_Avg_40 : 8|16@1+ (1,0) [0|65535] "mV"  MBMU,PC
 SG_ BAT_T_Max_40 : 24|8@1+ (1,-50) [-50|205] "℃"  MBMU,PC
 SG_ BAT_T_Min_40 : 32|8@1+ (1,-50) [-50|205] "℃"  MBMU,PC
 SG_ BAT_T_Avg_40 : 40|8@1+ (1,-50) [-50|205] "℃"  MBMU,PC
 SG_ BAT_T_Max_CSC_40 : 48|8@1+ (1,0) [0|255] ""  MBMU,PC
 SG_ BAT_T_Min_CSC_40 : 56|8@1+ (1,0) [0|255] ""  MBMU,PC

BO_ 2332360553 S2A_SUMDATA4__41: 8 SBMU
 SG_ CRC_S2A_S4_41 : 0|8@1+ (1,0) [0|255] ""  MBMU,PC
 SG_ BAT_Ucell_Avg_41 : 8|16@1+ (1,0) [0|65535] "mV"  MBMU,PC
 SG_ BAT_T_Max_41 : 24|8@1+ (1,-50) [-50|205] "℃"  MBMU,PC
 SG_ BAT_T_Min_41 : 32|8@1+ (1,-50) [-50|205] "℃"  MBMU,PC
 SG_ BAT_T_Avg_41 : 40|8@1+ (1,-50) [-50|205] "℃"  MBMU,PC
 SG_ BAT_T_Max_CSC_41 : 48|8@1+ (1,0) [0|255] ""  MBMU,PC
 SG_ BAT_T_Min_CSC_41 : 56|8@1+ (1,0) [0|255] ""  MBMU,PC

BO_ 2332360554 S2A_SUMDATA4__42: 8 SBMU
 SG_ CRC_S2A_S4_42 : 0|8@1+ (1,0) [0|255] ""  MBMU,PC
 SG_ BAT_Ucell_Avg_42 : 8|16@1+ (1,0) [0|65535] "mV"  MBMU,PC
 SG_ BAT_T_Max_42 : 24|8@1+ (1,-50) [-50|205] "℃"  MBMU,PC
 SG_ BAT_T_Min_42 : 32|8@1+ (1,-50) [-50|205] "℃"  MBMU,PC
 SG_ BAT_T_Avg_42 : 40|8@1+ (1,-50) [-50|205] "℃"  MBMU,PC
 SG_ BAT_T_Max_CSC_42 : 48|8@1+ (1,0) [0|255] ""  MBMU,PC
 SG_ BAT_T_Min_CSC_42 : 56|8@1+ (1,0) [0|255] ""  MBMU,PC

BO_ 2332360555 S2A_SUMDATA4__43: 8 SBMU
 SG_ CRC_S2A_S4_43 : 0|8@1+ (1,0) [0|255] ""  MBMU,PC
 SG_ BAT_Ucell_Avg_43 : 8|16@1+ (1,0) [0|65535] "mV"  MBMU,PC
 SG_ BAT_T_Max_43 : 24|8@1+ (1,-50) [-50|205] "℃"  MBMU,PC
 SG_ BAT_T_Min_43 : 32|8@1+ (1,-50) [-50|205] "℃"  MBMU,PC
 SG_ BAT_T_Avg_43 : 40|8@1+ (1,-50) [-50|205] "℃"  MBMU,PC
 SG_ BAT_T_Max_CSC_43 : 48|8@1+ (1,0) [0|255] ""  MBMU,PC
 SG_ BAT_T_Min_CSC_43 : 56|8@1+ (1,0) [0|255] ""  MBMU,PC

BO_ 2332360556 S2A_SUMDATA4__44: 8 SBMU
 SG_ CRC_S2A_S4_44 : 0|8@1+ (1,0) [0|255] ""  MBMU,PC
 SG_ BAT_Ucell_Avg_44 : 8|16@1+ (1,0) [0|65535] "mV"  MBMU,PC
 SG_ BAT_T_Max_44 : 24|8@1+ (1,-50) [-50|205] "℃"  MBMU,PC
 SG_ BAT_T_Min_44 : 32|8@1+ (1,-50) [-50|205] "℃"  MBMU,PC
 SG_ BAT_T_Avg_44 : 40|8@1+ (1,-50) [-50|205] "℃"  MBMU,PC
 SG_ BAT_T_Max_CSC_44 : 48|8@1+ (1,0) [0|255] ""  MBMU,PC
 SG_ BAT_T_Min_CSC_44 : 56|8@1+ (1,0) [0|255] ""  MBMU,PC

BO_ 2332360557 S2A_SUMDATA4__45: 8 SBMU
 SG_ CRC_S2A_S4_45 : 0|8@1+ (1,0) [0|255] ""  MBMU,PC
 SG_ BAT_Ucell_Avg_45 : 8|16@1+ (1,0) [0|65535] "mV"  MBMU,PC
 SG_ BAT_T_Max_45 : 24|8@1+ (1,-50) [-50|205] "℃"  MBMU,PC
 SG_ BAT_T_Min_45 : 32|8@1+ (1,-50) [-50|205] "℃"  MBMU,PC
 SG_ BAT_T_Avg_45 : 40|8@1+ (1,-50) [-50|205] "℃"  MBMU,PC
 SG_ BAT_T_Max_CSC_45 : 48|8@1+ (1,0) [0|255] ""  MBMU,PC
 SG_ BAT_T_Min_CSC_45 : 56|8@1+ (1,0) [0|255] ""  MBMU,PC

BO_ 2332360558 S2A_SUMDATA4__46: 8 SBMU
 SG_ CRC_S2A_S4_46 : 0|8@1+ (1,0) [0|255] ""  MBMU,PC
 SG_ BAT_Ucell_Avg_46 : 8|16@1+ (1,0) [0|65535] "mV"  MBMU,PC
 SG_ BAT_T_Max_46 : 24|8@1+ (1,-50) [-50|205] "℃"  MBMU,PC
 SG_ BAT_T_Min_46 : 32|8@1+ (1,-50) [-50|205] "℃"  MBMU,PC
 SG_ BAT_T_Avg_46 : 40|8@1+ (1,-50) [-50|205] "℃"  MBMU,PC
 SG_ BAT_T_Max_CSC_46 : 48|8@1+ (1,0) [0|255] ""  MBMU,PC
 SG_ BAT_T_Min_CSC_46 : 56|8@1+ (1,0) [0|255] ""  MBMU,PC

BO_ 2332360559 S2A_SUMDATA4__47: 8 SBMU
 SG_ CRC_S2A_S4_47 : 0|8@1+ (1,0) [0|255] ""  MBMU,PC
 SG_ BAT_Ucell_Avg_47 : 8|16@1+ (1,0) [0|65535] "mV"  MBMU,PC
 SG_ BAT_T_Max_47 : 24|8@1+ (1,-50) [-50|205] "℃"  MBMU,PC
 SG_ BAT_T_Min_47 : 32|8@1+ (1,-50) [-50|205] "℃"  MBMU,PC
 SG_ BAT_T_Avg_47 : 40|8@1+ (1,-50) [-50|205] "℃"  MBMU,PC
 SG_ BAT_T_Max_CSC_47 : 48|8@1+ (1,0) [0|255] ""  MBMU,PC
 SG_ BAT_T_Min_CSC_47 : 56|8@1+ (1,0) [0|255] ""  MBMU,PC

BO_ 2332360560 S2A_SUMDATA4__48: 8 SBMU
 SG_ CRC_S2A_S4_48 : 0|8@1+ (1,0) [0|255] ""  MBMU,PC
 SG_ BAT_Ucell_Avg_48 : 8|16@1+ (1,0) [0|65535] "mV"  MBMU,PC
 SG_ BAT_T_Max_48 : 24|8@1+ (1,-50) [-50|205] "℃"  MBMU,PC
 SG_ BAT_T_Min_48 : 32|8@1+ (1,-50) [-50|205] "℃"  MBMU,PC
 SG_ BAT_T_Avg_48 : 40|8@1+ (1,-50) [-50|205] "℃"  MBMU,PC
 SG_ BAT_T_Max_CSC_48 : 48|8@1+ (1,0) [0|255] ""  MBMU,PC
 SG_ BAT_T_Min_CSC_48 : 56|8@1+ (1,0) [0|255] ""  MBMU,PC

BO_ 2332360561 S2A_SUMDATA4__49: 8 SBMU
 SG_ CRC_S2A_S4_49 : 0|8@1+ (1,0) [0|255] ""  MBMU,PC
 SG_ BAT_Ucell_Avg_49 : 8|16@1+ (1,0) [0|65535] "mV"  MBMU,PC
 SG_ BAT_T_Max_49 : 24|8@1+ (1,-50) [-50|205] "℃"  MBMU,PC
 SG_ BAT_T_Min_49 : 32|8@1+ (1,-50) [-50|205] "℃"  MBMU,PC
 SG_ BAT_T_Avg_49 : 40|8@1+ (1,-50) [-50|205] "℃"  MBMU,PC
 SG_ BAT_T_Max_CSC_49 : 48|8@1+ (1,0) [0|255] ""  MBMU,PC
 SG_ BAT_T_Min_CSC_49 : 56|8@1+ (1,0) [0|255] ""  MBMU,PC

BO_ 2332360562 S2A_SUMDATA4__50: 8 SBMU
 SG_ CRC_S2A_S4_50 : 0|8@1+ (1,0) [0|255] ""  MBMU,PC
 SG_ BAT_Ucell_Avg_50 : 8|16@1+ (1,0) [0|65535] "mV"  MBMU,PC
 SG_ BAT_T_Max_50 : 24|8@1+ (1,-50) [-50|205] "℃"  MBMU,PC
 SG_ BAT_T_Min_50 : 32|8@1+ (1,-50) [-50|205] "℃"  MBMU,PC
 SG_ BAT_T_Avg_50 : 40|8@1+ (1,-50) [-50|205] "℃"  MBMU,PC
 SG_ BAT_T_Max_CSC_50 : 48|8@1+ (1,0) [0|255] ""  MBMU,PC
 SG_ BAT_T_Min_CSC_50 : 56|8@1+ (1,0) [0|255] ""  MBMU,PC

BO_ 2332360563 S2A_SUMDATA4__51: 8 SBMU
 SG_ CRC_S2A_S4_51 : 0|8@1+ (1,0) [0|255] ""  MBMU,PC
 SG_ BAT_Ucell_Avg_51 : 8|16@1+ (1,0) [0|65535] "mV"  MBMU,PC
 SG_ BAT_T_Max_51 : 24|8@1+ (1,-50) [-50|205] "℃"  MBMU,PC
 SG_ BAT_T_Min_51 : 32|8@1+ (1,-50) [-50|205] "℃"  MBMU,PC
 SG_ BAT_T_Avg_51 : 40|8@1+ (1,-50) [-50|205] "℃"  MBMU,PC
 SG_ BAT_T_Max_CSC_51 : 48|8@1+ (1,0) [0|255] ""  MBMU,PC
 SG_ BAT_T_Min_CSC_51 : 56|8@1+ (1,0) [0|255] ""  MBMU,PC

BO_ 2332360564 S2A_SUMDATA4__52: 8 SBMU
 SG_ CRC_S2A_S4_52 : 0|8@1+ (1,0) [0|255] ""  MBMU,PC
 SG_ BAT_Ucell_Avg_52 : 8|16@1+ (1,0) [0|65535] "mV"  MBMU,PC
 SG_ BAT_T_Max_52 : 24|8@1+ (1,-50) [-50|205] "℃"  MBMU,PC
 SG_ BAT_T_Min_52 : 32|8@1+ (1,-50) [-50|205] "℃"  MBMU,PC
 SG_ BAT_T_Avg_52 : 40|8@1+ (1,-50) [-50|205] "℃"  MBMU,PC
 SG_ BAT_T_Max_CSC_52 : 48|8@1+ (1,0) [0|255] ""  MBMU,PC
 SG_ BAT_T_Min_CSC_52 : 56|8@1+ (1,0) [0|255] ""  MBMU,PC

BO_ 2332360565 S2A_SUMDATA4__53: 8 SBMU
 SG_ CRC_S2A_S4_53 : 0|8@1+ (1,0) [0|255] ""  MBMU,PC
 SG_ BAT_Ucell_Avg_53 : 8|16@1+ (1,0) [0|65535] "mV"  MBMU,PC
 SG_ BAT_T_Max_53 : 24|8@1+ (1,-50) [-50|205] "℃"  MBMU,PC
 SG_ BAT_T_Min_53 : 32|8@1+ (1,-50) [-50|205] "℃"  MBMU,PC
 SG_ BAT_T_Avg_53 : 40|8@1+ (1,-50) [-50|205] "℃"  MBMU,PC
 SG_ BAT_T_Max_CSC_53 : 48|8@1+ (1,0) [0|255] ""  MBMU,PC
 SG_ BAT_T_Min_CSC_53 : 56|8@1+ (1,0) [0|255] ""  MBMU,PC

BO_ 2332360566 S2A_SUMDATA4__54: 8 SBMU
 SG_ CRC_S2A_S4_54 : 0|8@1+ (1,0) [0|255] ""  MBMU,PC
 SG_ BAT_Ucell_Avg_54 : 8|16@1+ (1,0) [0|65535] "mV"  MBMU,PC
 SG_ BAT_T_Max_54 : 24|8@1+ (1,-50) [-50|205] "℃"  MBMU,PC
 SG_ BAT_T_Min_54 : 32|8@1+ (1,-50) [-50|205] "℃"  MBMU,PC
 SG_ BAT_T_Avg_54 : 40|8@1+ (1,-50) [-50|205] "℃"  MBMU,PC
 SG_ BAT_T_Max_CSC_54 : 48|8@1+ (1,0) [0|255] ""  MBMU,PC
 SG_ BAT_T_Min_CSC_54 : 56|8@1+ (1,0) [0|255] ""  MBMU,PC

BO_ 2332360567 S2A_SUMDATA4__55: 8 SBMU
 SG_ CRC_S2A_S4_55 : 0|8@1+ (1,0) [0|255] ""  MBMU,PC
 SG_ BAT_Ucell_Avg_55 : 8|16@1+ (1,0) [0|65535] "mV"  MBMU,PC
 SG_ BAT_T_Max_55 : 24|8@1+ (1,-50) [-50|205] "℃"  MBMU,PC
 SG_ BAT_T_Min_55 : 32|8@1+ (1,-50) [-50|205] "℃"  MBMU,PC
 SG_ BAT_T_Avg_55 : 40|8@1+ (1,-50) [-50|205] "℃"  MBMU,PC
 SG_ BAT_T_Max_CSC_55 : 48|8@1+ (1,0) [0|255] ""  MBMU,PC
 SG_ BAT_T_Min_CSC_55 : 56|8@1+ (1,0) [0|255] ""  MBMU,PC

BO_ 2332360568 S2A_SUMDATA4__56: 8 SBMU
 SG_ CRC_S2A_S4_56 : 0|8@1+ (1,0) [0|255] ""  MBMU,PC
 SG_ BAT_Ucell_Avg_56 : 8|16@1+ (1,0) [0|65535] "mV"  MBMU,PC
 SG_ BAT_T_Max_56 : 24|8@1+ (1,-50) [-50|205] "℃"  MBMU,PC
 SG_ BAT_T_Min_56 : 32|8@1+ (1,-50) [-50|205] "℃"  MBMU,PC
 SG_ BAT_T_Avg_56 : 40|8@1+ (1,-50) [-50|205] "℃"  MBMU,PC
 SG_ BAT_T_Max_CSC_56 : 48|8@1+ (1,0) [0|255] ""  MBMU,PC
 SG_ BAT_T_Min_CSC_56 : 56|8@1+ (1,0) [0|255] ""  MBMU,PC

BO_ 2332360569 S2A_SUMDATA4__57: 8 SBMU
 SG_ CRC_S2A_S4_57 : 0|8@1+ (1,0) [0|255] ""  MBMU,PC
 SG_ BAT_Ucell_Avg_57 : 8|16@1+ (1,0) [0|65535] "mV"  MBMU,PC
 SG_ BAT_T_Max_57 : 24|8@1+ (1,-50) [-50|205] "℃"  MBMU,PC
 SG_ BAT_T_Min_57 : 32|8@1+ (1,-50) [-50|205] "℃"  MBMU,PC
 SG_ BAT_T_Avg_57 : 40|8@1+ (1,-50) [-50|205] "℃"  MBMU,PC
 SG_ BAT_T_Max_CSC_57 : 48|8@1+ (1,0) [0|255] ""  MBMU,PC
 SG_ BAT_T_Min_CSC_57 : 56|8@1+ (1,0) [0|255] ""  MBMU,PC

BO_ 2332360570 S2A_SUMDATA4__58: 8 SBMU
 SG_ CRC_S2A_S4_58 : 0|8@1+ (1,0) [0|255] ""  MBMU,PC
 SG_ BAT_Ucell_Avg_58 : 8|16@1+ (1,0) [0|65535] "mV"  MBMU,PC
 SG_ BAT_T_Max_58 : 24|8@1+ (1,-50) [-50|205] "℃"  MBMU,PC
 SG_ BAT_T_Min_58 : 32|8@1+ (1,-50) [-50|205] "℃"  MBMU,PC
 SG_ BAT_T_Avg_58 : 40|8@1+ (1,-50) [-50|205] "℃"  MBMU,PC
 SG_ BAT_T_Max_CSC_58 : 48|8@1+ (1,0) [0|255] ""  MBMU,PC
 SG_ BAT_T_Min_CSC_58 : 56|8@1+ (1,0) [0|255] ""  MBMU,PC

BO_ 2332360571 S2A_SUMDATA4__59: 8 SBMU
 SG_ CRC_S2A_S4_59 : 0|8@1+ (1,0) [0|255] ""  MBMU,PC
 SG_ BAT_Ucell_Avg_59 : 8|16@1+ (1,0) [0|65535] "mV"  MBMU,PC
 SG_ BAT_T_Max_59 : 24|8@1+ (1,-50) [-50|205] "℃"  MBMU,PC
 SG_ BAT_T_Min_59 : 32|8@1+ (1,-50) [-50|205] "℃"  MBMU,PC
 SG_ BAT_T_Avg_59 : 40|8@1+ (1,-50) [-50|205] "℃"  MBMU,PC
 SG_ BAT_T_Max_CSC_59 : 48|8@1+ (1,0) [0|255] ""  MBMU,PC
 SG_ BAT_T_Min_CSC_59 : 56|8@1+ (1,0) [0|255] ""  MBMU,PC

BO_ 2332360572 S2A_SUMDATA4__60: 8 SBMU
 SG_ CRC_S2A_S4_60 : 0|8@1+ (1,0) [0|255] ""  MBMU,PC
 SG_ BAT_Ucell_Avg_60 : 8|16@1+ (1,0) [0|65535] "mV"  MBMU,PC
 SG_ BAT_T_Max_60 : 24|8@1+ (1,-50) [-50|205] "℃"  MBMU,PC
 SG_ BAT_T_Min_60 : 32|8@1+ (1,-50) [-50|205] "℃"  MBMU,PC
 SG_ BAT_T_Avg_60 : 40|8@1+ (1,-50) [-50|205] "℃"  MBMU,PC
 SG_ BAT_T_Max_CSC_60 : 48|8@1+ (1,0) [0|255] ""  MBMU,PC
 SG_ BAT_T_Min_CSC_60 : 56|8@1+ (1,0) [0|255] ""  MBMU,PC

BO_ 2332360573 S2A_SUMDATA4__61: 8 SBMU
 SG_ CRC_S2A_S4_61 : 0|8@1+ (1,0) [0|255] ""  MBMU,PC
 SG_ BAT_Ucell_Avg_61 : 8|16@1+ (1,0) [0|65535] "mV"  MBMU,PC
 SG_ BAT_T_Max_61 : 24|8@1+ (1,-50) [-50|205] "℃"  MBMU,PC
 SG_ BAT_T_Min_61 : 32|8@1+ (1,-50) [-50|205] "℃"  MBMU,PC
 SG_ BAT_T_Avg_61 : 40|8@1+ (1,-50) [-50|205] "℃"  MBMU,PC
 SG_ BAT_T_Max_CSC_61 : 48|8@1+ (1,0) [0|255] ""  MBMU,PC
 SG_ BAT_T_Min_CSC_61 : 56|8@1+ (1,0) [0|255] ""  MBMU,PC

BO_ 2332360574 S2A_SUMDATA4__62: 8 SBMU
 SG_ CRC_S2A_S4_62 : 0|8@1+ (1,0) [0|255] ""  MBMU,PC
 SG_ BAT_Ucell_Avg_62 : 8|16@1+ (1,0) [0|65535] "mV"  MBMU,PC
 SG_ BAT_T_Max_62 : 24|8@1+ (1,-50) [-50|205] "℃"  MBMU,PC
 SG_ BAT_T_Min_62 : 32|8@1+ (1,-50) [-50|205] "℃"  MBMU,PC
 SG_ BAT_T_Avg_62 : 40|8@1+ (1,-50) [-50|205] "℃"  MBMU,PC
 SG_ BAT_T_Max_CSC_62 : 48|8@1+ (1,0) [0|255] ""  MBMU,PC
 SG_ BAT_T_Min_CSC_62 : 56|8@1+ (1,0) [0|255] ""  MBMU,PC

BO_ 2332360575 S2A_SUMDATA4__63: 8 SBMU
 SG_ CRC_S2A_S4_63 : 0|8@1+ (1,0) [0|255] ""  MBMU,PC
 SG_ BAT_Ucell_Avg_63 : 8|16@1+ (1,0) [0|65535] "mV"  MBMU,PC
 SG_ BAT_T_Max_63 : 24|8@1+ (1,-50) [-50|205] "℃"  MBMU,PC
 SG_ BAT_T_Min_63 : 32|8@1+ (1,-50) [-50|205] "℃"  MBMU,PC
 SG_ BAT_T_Avg_63 : 40|8@1+ (1,-50) [-50|205] "℃"  MBMU,PC
 SG_ BAT_T_Max_CSC_63 : 48|8@1+ (1,0) [0|255] ""  MBMU,PC
 SG_ BAT_T_Min_CSC_63 : 56|8@1+ (1,0) [0|255] ""  MBMU,PC

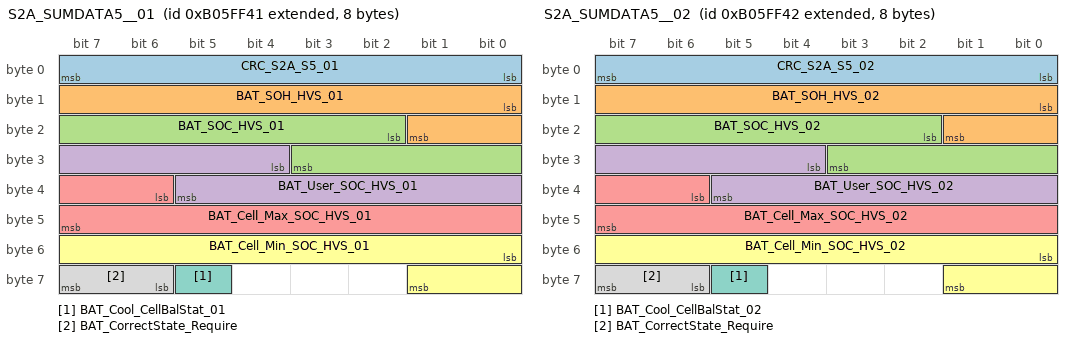
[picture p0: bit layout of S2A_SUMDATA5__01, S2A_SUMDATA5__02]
BO_ 2332426049 S2A_SUMDATA5__01: 8 SBMU
 SG_ CRC_S2A_S5_01 : 0|8@1+ (1,0) [0|255] ""  MBMU,PC
 SG_ BAT_SOH_HVS_01 : 8|10@1+ (0.1,0) [0|102.3] "%"  MBMU,PC
 SG_ BAT_SOC_HVS_01 : 18|10@1+ (0.1,0) [0|102.3] "%"  MBMU,PC
 SG_ BAT_User_SOC_HVS_01 : 28|10@1+ (0.1,0) [0|102.3] "%"  MBMU,PC
 SG_ BAT_Cell_Max_SOC_HVS_01 : 38|10@1+ (0.1,0) [0|102.3] "%"  MBMU,PC
 SG_ BAT_Cell_Min_SOC_HVS_01 : 48|10@1+ (0.1,0) [0|102.3] "%"  MBMU,PC
 SG_ BAT_Cool_CellBalStat_01 : 61|1@1+ (1,0) [0|1] ""  MBMU,PC
 SG_ BAT_CorrectState_Require : 62|2@1+ (1,0) [0|3] ""  MBMU,PC

BO_ 2332426050 S2A_SUMDATA5__02: 8 SBMU
 SG_ CRC_S2A_S5_02 : 0|8@1+ (1,0) [0|255] ""  MBMU,PC
 SG_ BAT_SOH_HVS_02 : 8|10@1+ (0.1,0) [0|102.3] "%"  MBMU,PC
 SG_ BAT_SOC_HVS_02 : 18|10@1+ (0.1,0) [0|102.3] "%"  MBMU,PC
 SG_ BAT_User_SOC_HVS_02 : 28|10@1+ (0.1,0) [0|102.3] "%"  MBMU,PC
 SG_ BAT_Cell_Max_SOC_HVS_02 : 38|10@1+ (0.1,0) [0|102.3] "%"  MBMU,PC
 SG_ BAT_Cell_Min_SOC_HVS_02 : 48|10@1+ (0.1,0) [0|102.3] "%"  MBMU,PC
 SG_ BAT_Cool_CellBalStat_02 : 61|1@1+ (1,0) [0|1] ""  MBMU,PC
 SG_ BAT_CorrectState_Require : 62|2@1+ (1,0) [0|3] ""  MBMU,PC

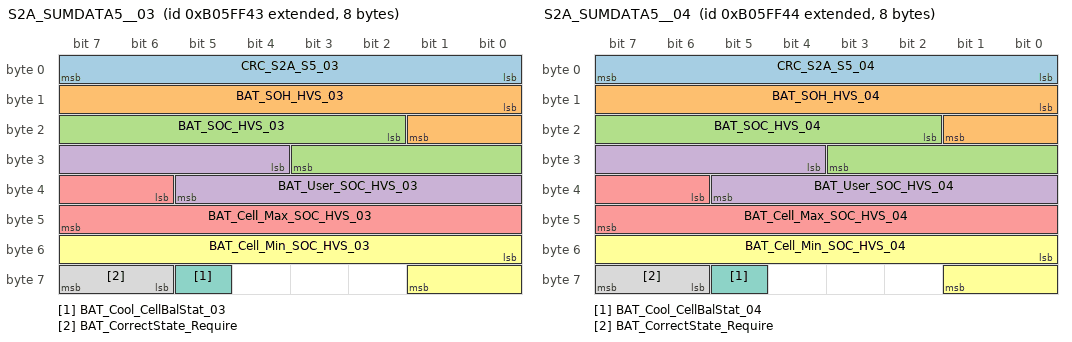
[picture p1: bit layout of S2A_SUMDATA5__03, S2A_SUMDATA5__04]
BO_ 2332426051 S2A_SUMDATA5__03: 8 SBMU
 SG_ CRC_S2A_S5_03 : 0|8@1+ (1,0) [0|255] ""  MBMU,PC
 SG_ BAT_SOH_HVS_03 : 8|10@1+ (0.1,0) [0|102.3] "%"  MBMU,PC
 SG_ BAT_SOC_HVS_03 : 18|10@1+ (0.1,0) [0|102.3] "%"  MBMU,PC
 SG_ BAT_User_SOC_HVS_03 : 28|10@1+ (0.1,0) [0|102.3] "%"  MBMU,PC
 SG_ BAT_Cell_Max_SOC_HVS_03 : 38|10@1+ (0.1,0) [0|102.3] "%"  MBMU,PC
 SG_ BAT_Cell_Min_SOC_HVS_03 : 48|10@1+ (0.1,0) [0|102.3] "%"  MBMU,PC
 SG_ BAT_Cool_CellBalStat_03 : 61|1@1+ (1,0) [0|1] ""  MBMU,PC
 SG_ BAT_CorrectState_Require : 62|2@1+ (1,0) [0|3] ""  MBMU,PC

BO_ 2332426052 S2A_SUMDATA5__04: 8 SBMU
 SG_ CRC_S2A_S5_04 : 0|8@1+ (1,0) [0|255] ""  MBMU,PC
 SG_ BAT_SOH_HVS_04 : 8|10@1+ (0.1,0) [0|102.3] "%"  MBMU,PC
 SG_ BAT_SOC_HVS_04 : 18|10@1+ (0.1,0) [0|102.3] "%"  MBMU,PC
 SG_ BAT_User_SOC_HVS_04 : 28|10@1+ (0.1,0) [0|102.3] "%"  MBMU,PC
 SG_ BAT_Cell_Max_SOC_HVS_04 : 38|10@1+ (0.1,0) [0|102.3] "%"  MBMU,PC
 SG_ BAT_Cell_Min_SOC_HVS_04 : 48|10@1+ (0.1,0) [0|102.3] "%"  MBMU,PC
 SG_ BAT_Cool_CellBalStat_04 : 61|1@1+ (1,0) [0|1] ""  MBMU,PC
 SG_ BAT_CorrectState_Require : 62|2@1+ (1,0) [0|3] ""  MBMU,PC

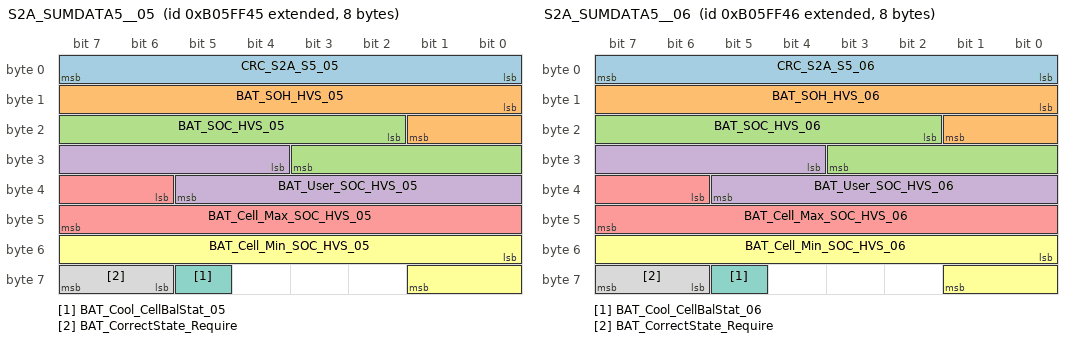
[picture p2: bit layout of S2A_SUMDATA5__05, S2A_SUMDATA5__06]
BO_ 2332426053 S2A_SUMDATA5__05: 8 SBMU
 SG_ CRC_S2A_S5_05 : 0|8@1+ (1,0) [0|255] ""  MBMU,PC
 SG_ BAT_SOH_HVS_05 : 8|10@1+ (0.1,0) [0|102.3] "%"  MBMU,PC
 SG_ BAT_SOC_HVS_05 : 18|10@1+ (0.1,0) [0|102.3] "%"  MBMU,PC
 SG_ BAT_User_SOC_HVS_05 : 28|10@1+ (0.1,0) [0|102.3] "%"  MBMU,PC
 SG_ BAT_Cell_Max_SOC_HVS_05 : 38|10@1+ (0.1,0) [0|102.3] "%"  MBMU,PC
 SG_ BAT_Cell_Min_SOC_HVS_05 : 48|10@1+ (0.1,0) [0|102.3] "%"  MBMU,PC
 SG_ BAT_Cool_CellBalStat_05 : 61|1@1+ (1,0) [0|1] ""  MBMU,PC
 SG_ BAT_CorrectState_Require : 62|2@1+ (1,0) [0|3] ""  MBMU,PC

BO_ 2332426054 S2A_SUMDATA5__06: 8 SBMU
 SG_ CRC_S2A_S5_06 : 0|8@1+ (1,0) [0|255] ""  MBMU,PC
 SG_ BAT_SOH_HVS_06 : 8|10@1+ (0.1,0) [0|102.3] "%"  MBMU,PC
 SG_ BAT_SOC_HVS_06 : 18|10@1+ (0.1,0) [0|102.3] "%"  MBMU,PC
 SG_ BAT_User_SOC_HVS_06 : 28|10@1+ (0.1,0) [0|102.3] "%"  MBMU,PC
 SG_ BAT_Cell_Max_SOC_HVS_06 : 38|10@1+ (0.1,0) [0|102.3] "%"  MBMU,PC
 SG_ BAT_Cell_Min_SOC_HVS_06 : 48|10@1+ (0.1,0) [0|102.3] "%"  MBMU,PC
 SG_ BAT_Cool_CellBalStat_06 : 61|1@1+ (1,0) [0|1] ""  MBMU,PC
 SG_ BAT_CorrectState_Require : 62|2@1+ (1,0) [0|3] ""  MBMU,PC

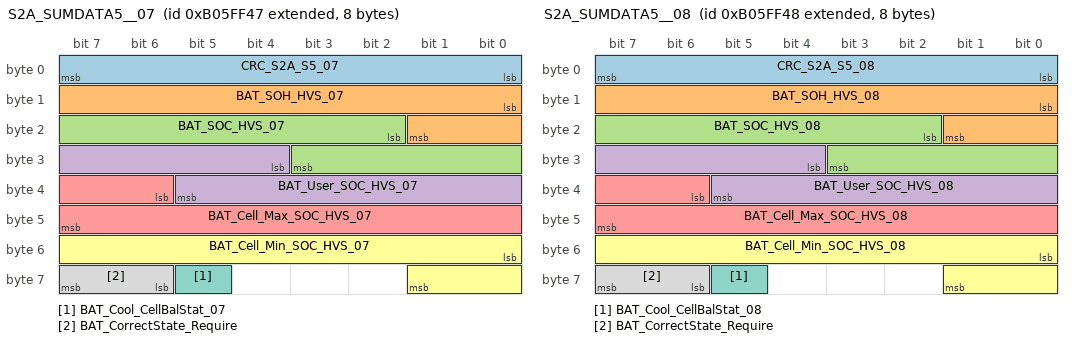
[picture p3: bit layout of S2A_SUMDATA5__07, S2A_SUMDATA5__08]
BO_ 2332426055 S2A_SUMDATA5__07: 8 SBMU
 SG_ CRC_S2A_S5_07 : 0|8@1+ (1,0) [0|255] ""  MBMU,PC
 SG_ BAT_SOH_HVS_07 : 8|10@1+ (0.1,0) [0|102.3] "%"  MBMU,PC
 SG_ BAT_SOC_HVS_07 : 18|10@1+ (0.1,0) [0|102.3] "%"  MBMU,PC
 SG_ BAT_User_SOC_HVS_07 : 28|10@1+ (0.1,0) [0|102.3] "%"  MBMU,PC
 SG_ BAT_Cell_Max_SOC_HVS_07 : 38|10@1+ (0.1,0) [0|102.3] "%"  MBMU,PC
 SG_ BAT_Cell_Min_SOC_HVS_07 : 48|10@1+ (0.1,0) [0|102.3] "%"  MBMU,PC
 SG_ BAT_Cool_CellBalStat_07 : 61|1@1+ (1,0) [0|1] ""  MBMU,PC
 SG_ BAT_CorrectState_Require : 62|2@1+ (1,0) [0|3] ""  MBMU,PC

BO_ 2332426056 S2A_SUMDATA5__08: 8 SBMU
 SG_ CRC_S2A_S5_08 : 0|8@1+ (1,0) [0|255] ""  MBMU,PC
 SG_ BAT_SOH_HVS_08 : 8|10@1+ (0.1,0) [0|102.3] "%"  MBMU,PC
 SG_ BAT_SOC_HVS_08 : 18|10@1+ (0.1,0) [0|102.3] "%"  MBMU,PC
 SG_ BAT_User_SOC_HVS_08 : 28|10@1+ (0.1,0) [0|102.3] "%"  MBMU,PC
 SG_ BAT_Cell_Max_SOC_HVS_08 : 38|10@1+ (0.1,0) [0|102.3] "%"  MBMU,PC
 SG_ BAT_Cell_Min_SOC_HVS_08 : 48|10@1+ (0.1,0) [0|102.3] "%"  MBMU,PC
 SG_ BAT_Cool_CellBalStat_08 : 61|1@1+ (1,0) [0|1] ""  MBMU,PC
 SG_ BAT_CorrectState_Require : 62|2@1+ (1,0) [0|3] ""  MBMU,PC

BO_ 2332426057 S2A_SUMDATA5__09: 8 SBMU
 SG_ CRC_S2A_S5_09 : 0|8@1+ (1,0) [0|255] ""  MBMU,PC
 SG_ BAT_SOH_HVS_09 : 8|10@1+ (0.1,0) [0|102.3] "%"  MBMU,PC
 SG_ BAT_SOC_HVS_09 : 18|10@1+ (0.1,0) [0|102.3] "%"  MBMU,PC
 SG_ BAT_User_SOC_HVS_09 : 28|10@1+ (0.1,0) [0|102.3] "%"  MBMU,PC
 SG_ BAT_Cell_Max_SOC_HVS_09 : 38|10@1+ (0.1,0) [0|102.3] "%"  MBMU,PC
 SG_ BAT_Cell_Min_SOC_HVS_09 : 48|10@1+ (0.1,0) [0|102.3] "%"  MBMU,PC
 SG_ BAT_Cool_CellBalStat_09 : 61|1@1+ (1,0) [0|1] ""  MBMU,PC
 SG_ BAT_CorrectState_Require : 62|2@1+ (1,0) [0|3] ""  MBMU,PC

BO_ 2332426058 S2A_SUMDATA5__10: 8 SBMU
 SG_ CRC_S2A_S5_10 : 0|8@1+ (1,0) [0|255] ""  MBMU,PC
 SG_ BAT_SOH_HVS_10 : 8|10@1+ (0.1,0) [0|102.3] "%"  MBMU,PC
 SG_ BAT_SOC_HVS_10 : 18|10@1+ (0.1,0) [0|102.3] "%"  MBMU,PC
 SG_ BAT_User_SOC_HVS_10 : 28|10@1+ (0.1,0) [0|102.3] "%"  MBMU,PC
 SG_ BAT_Cell_Max_SOC_HVS_10 : 38|10@1+ (0.1,0) [0|102.3] "%"  MBMU,PC
 SG_ BAT_Cell_Min_SOC_HVS_10 : 48|10@1+ (0.1,0) [0|102.3] "%"  MBMU,PC
 SG_ BAT_Cool_CellBalStat_10 : 61|1@1+ (1,0) [0|1] ""  MBMU,PC
 SG_ BAT_CorrectState_Require : 62|2@1+ (1,0) [0|3] ""  MBMU,PC

BO_ 2332426059 S2A_SUMDATA5__11: 8 SBMU
 SG_ CRC_S2A_S5_11 : 0|8@1+ (1,0) [0|255] ""  MBMU,PC
 SG_ BAT_SOH_HVS_11 : 8|10@1+ (0.1,0) [0|102.3] "%"  MBMU,PC
 SG_ BAT_SOC_HVS_11 : 18|10@1+ (0.1,0) [0|102.3] "%"  MBMU,PC
 SG_ BAT_User_SOC_HVS_11 : 28|10@1+ (0.1,0) [0|102.3] "%"  MBMU,PC
 SG_ BAT_Cell_Max_SOC_HVS_11 : 38|10@1+ (0.1,0) [0|102.3] "%"  MBMU,PC
 SG_ BAT_Cell_Min_SOC_HVS_11 : 48|10@1+ (0.1,0) [0|102.3] "%"  MBMU,PC
 SG_ BAT_Cool_CellBalStat_11 : 61|1@1+ (1,0) [0|1] ""  MBMU,PC
 SG_ BAT_CorrectState_Require : 62|2@1+ (1,0) [0|3] ""  MBMU,PC

BO_ 2332426060 S2A_SUMDATA5__12: 8 SBMU
 SG_ CRC_S2A_S5_12 : 0|8@1+ (1,0) [0|255] ""  MBMU,PC
 SG_ BAT_SOH_HVS_12 : 8|10@1+ (0.1,0) [0|102.3] "%"  MBMU,PC
 SG_ BAT_SOC_HVS_12 : 18|10@1+ (0.1,0) [0|102.3] "%"  MBMU,PC
 SG_ BAT_User_SOC_HVS_12 : 28|10@1+ (0.1,0) [0|102.3] "%"  MBMU,PC
 SG_ BAT_Cell_Max_SOC_HVS_12 : 38|10@1+ (0.1,0) [0|102.3] "%"  MBMU,PC
 SG_ BAT_Cell_Min_SOC_HVS_12 : 48|10@1+ (0.1,0) [0|102.3] "%"  MBMU,PC
 SG_ BAT_Cool_CellBalStat_12 : 61|1@1+ (1,0) [0|1] ""  MBMU,PC
 SG_ BAT_CorrectState_Require : 62|2@1+ (1,0) [0|3] ""  MBMU,PC

BO_ 2332426061 S2A_SUMDATA5__13: 8 SBMU
 SG_ CRC_S2A_S5_13 : 0|8@1+ (1,0) [0|255] ""  MBMU,PC
 SG_ BAT_SOH_HVS_13 : 8|10@1+ (0.1,0) [0|102.3] "%"  MBMU,PC
 SG_ BAT_SOC_HVS_13 : 18|10@1+ (0.1,0) [0|102.3] "%"  MBMU,PC
 SG_ BAT_User_SOC_HVS_13 : 28|10@1+ (0.1,0) [0|102.3] "%"  MBMU,PC
 SG_ BAT_Cell_Max_SOC_HVS_13 : 38|10@1+ (0.1,0) [0|102.3] "%"  MBMU,PC
 SG_ BAT_Cell_Min_SOC_HVS_13 : 48|10@1+ (0.1,0) [0|102.3] "%"  MBMU,PC
 SG_ BAT_Cool_CellBalStat_13 : 61|1@1+ (1,0) [0|1] ""  MBMU,PC
 SG_ BAT_CorrectState_Require : 62|2@1+ (1,0) [0|3] ""  MBMU,PC

BO_ 2332426062 S2A_SUMDATA5__14: 8 SBMU
 SG_ CRC_S2A_S5_14 : 0|8@1+ (1,0) [0|255] ""  MBMU,PC
 SG_ BAT_SOH_HVS_14 : 8|10@1+ (0.1,0) [0|102.3] "%"  MBMU,PC
 SG_ BAT_SOC_HVS_14 : 18|10@1+ (0.1,0) [0|102.3] "%"  MBMU,PC
 SG_ BAT_User_SOC_HVS_14 : 28|10@1+ (0.1,0) [0|102.3] "%"  MBMU,PC
 SG_ BAT_Cell_Max_SOC_HVS_14 : 38|10@1+ (0.1,0) [0|102.3] "%"  MBMU,PC
 SG_ BAT_Cell_Min_SOC_HVS_14 : 48|10@1+ (0.1,0) [0|102.3] "%"  MBMU,PC
 SG_ BAT_Cool_CellBalStat_14 : 61|1@1+ (1,0) [0|1] ""  MBMU,PC
 SG_ BAT_CorrectState_Require : 62|2@1+ (1,0) [0|3] ""  MBMU,PC

BO_ 2332426063 S2A_SUMDATA5__15: 8 SBMU
 SG_ CRC_S2A_S5_15 : 0|8@1+ (1,0) [0|255] ""  MBMU,PC
 SG_ BAT_SOH_HVS_15 : 8|10@1+ (0.1,0) [0|102.3] "%"  MBMU,PC
 SG_ BAT_SOC_HVS_15 : 18|10@1+ (0.1,0) [0|102.3] "%"  MBMU,PC
 SG_ BAT_User_SOC_HVS_15 : 28|10@1+ (0.1,0) [0|102.3] "%"  MBMU,PC
 SG_ BAT_Cell_Max_SOC_HVS_15 : 38|10@1+ (0.1,0) [0|102.3] "%"  MBMU,PC
 SG_ BAT_Cell_Min_SOC_HVS_15 : 48|10@1+ (0.1,0) [0|102.3] "%"  MBMU,PC
 SG_ BAT_Cool_CellBalStat_15 : 61|1@1+ (1,0) [0|1] ""  MBMU,PC
 SG_ BAT_CorrectState_Require : 62|2@1+ (1,0) [0|3] ""  MBMU,PC

BO_ 2332426064 S2A_SUMDATA5__16: 8 SBMU
 SG_ CRC_S2A_S5_16 : 0|8@1+ (1,0) [0|255] ""  MBMU,PC
 SG_ BAT_SOH_HVS_16 : 8|10@1+ (0.1,0) [0|102.3] "%"  MBMU,PC
 SG_ BAT_SOC_HVS_16 : 18|10@1+ (0.1,0) [0|102.3] "%"  MBMU,PC
 SG_ BAT_User_SOC_HVS_16 : 28|10@1+ (0.1,0) [0|102.3] "%"  MBMU,PC
 SG_ BAT_Cell_Max_SOC_HVS_16 : 38|10@1+ (0.1,0) [0|102.3] "%"  MBMU,PC
 SG_ BAT_Cell_Min_SOC_HVS_16 : 48|10@1+ (0.1,0) [0|102.3] "%"  MBMU,PC
 SG_ BAT_Cool_CellBalStat_16 : 61|1@1+ (1,0) [0|1] ""  MBMU,PC
 SG_ BAT_CorrectState_Require : 62|2@1+ (1,0) [0|3] ""  MBMU,PC

BO_ 2332426065 S2A_SUMDATA5__17: 8 SBMU
 SG_ CRC_S2A_S5_17 : 0|8@1+ (1,0) [0|255] ""  MBMU,PC
 SG_ BAT_SOH_HVS_17 : 8|10@1+ (0.1,0) [0|102.3] "%"  MBMU,PC
 SG_ BAT_SOC_HVS_17 : 18|10@1+ (0.1,0) [0|102.3] "%"  MBMU,PC
 SG_ BAT_User_SOC_HVS_17 : 28|10@1+ (0.1,0) [0|102.3] "%"  MBMU,PC
 SG_ BAT_Cell_Max_SOC_HVS_17 : 38|10@1+ (0.1,0) [0|102.3] "%"  MBMU,PC
 SG_ BAT_Cell_Min_SOC_HVS_17 : 48|10@1+ (0.1,0) [0|102.3] "%"  MBMU,PC
 SG_ BAT_Cool_CellBalStat_17 : 61|1@1+ (1,0) [0|1] ""  MBMU,PC
 SG_ BAT_CorrectState_Require : 62|2@1+ (1,0) [0|3] ""  MBMU,PC

BO_ 2332426066 S2A_SUMDATA5__18: 8 SBMU
 SG_ CRC_S2A_S5_18 : 0|8@1+ (1,0) [0|255] ""  MBMU,PC
 SG_ BAT_SOH_HVS_18 : 8|10@1+ (0.1,0) [0|102.3] "%"  MBMU,PC
 SG_ BAT_SOC_HVS_18 : 18|10@1+ (0.1,0) [0|102.3] "%"  MBMU,PC
 SG_ BAT_User_SOC_HVS_18 : 28|10@1+ (0.1,0) [0|102.3] "%"  MBMU,PC
 SG_ BAT_Cell_Max_SOC_HVS_18 : 38|10@1+ (0.1,0) [0|102.3] "%"  MBMU,PC
 SG_ BAT_Cell_Min_SOC_HVS_18 : 48|10@1+ (0.1,0) [0|102.3] "%"  MBMU,PC
 SG_ BAT_Cool_CellBalStat_18 : 61|1@1+ (1,0) [0|1] ""  MBMU,PC
 SG_ BAT_CorrectState_Require : 62|2@1+ (1,0) [0|3] ""  MBMU,PC

BO_ 2332426067 S2A_SUMDATA5__19: 8 SBMU
 SG_ CRC_S2A_S5_19 : 0|8@1+ (1,0) [0|255] ""  MBMU,PC
 SG_ BAT_SOH_HVS_19 : 8|10@1+ (0.1,0) [0|102.3] "%"  MBMU,PC
 SG_ BAT_SOC_HVS_19 : 18|10@1+ (0.1,0) [0|102.3] "%"  MBMU,PC
 SG_ BAT_User_SOC_HVS_19 : 28|10@1+ (0.1,0) [0|102.3] "%"  MBMU,PC
 SG_ BAT_Cell_Max_SOC_HVS_19 : 38|10@1+ (0.1,0) [0|102.3] "%"  MBMU,PC
 SG_ BAT_Cell_Min_SOC_HVS_19 : 48|10@1+ (0.1,0) [0|102.3] "%"  MBMU,PC
 SG_ BAT_Cool_CellBalStat_19 : 61|1@1+ (1,0) [0|1] ""  MBMU,PC
 SG_ BAT_CorrectState_Require : 62|2@1+ (1,0) [0|3] ""  MBMU,PC

BO_ 2332426068 S2A_SUMDATA5__20: 8 SBMU
 SG_ CRC_S2A_S5_20 : 0|8@1+ (1,0) [0|255] ""  MBMU,PC
 SG_ BAT_SOH_HVS_20 : 8|10@1+ (0.1,0) [0|102.3] "%"  MBMU,PC
 SG_ BAT_SOC_HVS_20 : 18|10@1+ (0.1,0) [0|102.3] "%"  MBMU,PC
 SG_ BAT_User_SOC_HVS_20 : 28|10@1+ (0.1,0) [0|102.3] "%"  MBMU,PC
 SG_ BAT_Cell_Max_SOC_HVS_20 : 38|10@1+ (0.1,0) [0|102.3] "%"  MBMU,PC
 SG_ BAT_Cell_Min_SOC_HVS_20 : 48|10@1+ (0.1,0) [0|102.3] "%"  MBMU,PC
 SG_ BAT_Cool_CellBalStat_20 : 61|1@1+ (1,0) [0|1] ""  MBMU,PC
 SG_ BAT_CorrectState_Require : 62|2@1+ (1,0) [0|3] ""  MBMU,PC

BO_ 2332426069 S2A_SUMDATA5__21: 8 SBMU
 SG_ CRC_S2A_S5_21 : 0|8@1+ (1,0) [0|255] ""  MBMU,PC
 SG_ BAT_SOH_HVS_21 : 8|10@1+ (0.1,0) [0|102.3] "%"  MBMU,PC
 SG_ BAT_SOC_HVS_21 : 18|10@1+ (0.1,0) [0|102.3] "%"  MBMU,PC
 SG_ BAT_User_SOC_HVS_21 : 28|10@1+ (0.1,0) [0|102.3] "%"  MBMU,PC
 SG_ BAT_Cell_Max_SOC_HVS_21 : 38|10@1+ (0.1,0) [0|102.3] "%"  MBMU,PC
 SG_ BAT_Cell_Min_SOC_HVS_21 : 48|10@1+ (0.1,0) [0|102.3] "%"  MBMU,PC
 SG_ BAT_Cool_CellBalStat_21 : 61|1@1+ (1,0) [0|1] ""  MBMU,PC
 SG_ BAT_CorrectState_Require : 62|2@1+ (1,0) [0|3] ""  MBMU,PC

BO_ 2332426070 S2A_SUMDATA5__22: 8 SBMU
 SG_ CRC_S2A_S5_22 : 0|8@1+ (1,0) [0|255] ""  MBMU,PC
 SG_ BAT_SOH_HVS_22 : 8|10@1+ (0.1,0) [0|102.3] "%"  MBMU,PC
 SG_ BAT_SOC_HVS_22 : 18|10@1+ (0.1,0) [0|102.3] "%"  MBMU,PC
 SG_ BAT_User_SOC_HVS_22 : 28|10@1+ (0.1,0) [0|102.3] "%"  MBMU,PC
 SG_ BAT_Cell_Max_SOC_HVS_22 : 38|10@1+ (0.1,0) [0|102.3] "%"  MBMU,PC
 SG_ BAT_Cell_Min_SOC_HVS_22 : 48|10@1+ (0.1,0) [0|102.3] "%"  MBMU,PC
 SG_ BAT_Cool_CellBalStat_22 : 61|1@1+ (1,0) [0|1] ""  MBMU,PC
 SG_ BAT_CorrectState_Require : 62|2@1+ (1,0) [0|3] ""  MBMU,PC

BO_ 2332426071 S2A_SUMDATA5__23: 8 SBMU
 SG_ CRC_S2A_S5_23 : 0|8@1+ (1,0) [0|255] ""  MBMU,PC
 SG_ BAT_SOH_HVS_23 : 8|10@1+ (0.1,0) [0|102.3] "%"  MBMU,PC
 SG_ BAT_SOC_HVS_23 : 18|10@1+ (0.1,0) [0|102.3] "%"  MBMU,PC
 SG_ BAT_User_SOC_HVS_23 : 28|10@1+ (0.1,0) [0|102.3] "%"  MBMU,PC
 SG_ BAT_Cell_Max_SOC_HVS_23 : 38|10@1+ (0.1,0) [0|102.3] "%"  MBMU,PC
 SG_ BAT_Cell_Min_SOC_HVS_23 : 48|10@1+ (0.1,0) [0|102.3] "%"  MBMU,PC
 SG_ BAT_Cool_CellBalStat_23 : 61|1@1+ (1,0) [0|1] ""  MBMU,PC
 SG_ BAT_CorrectState_Require : 62|2@1+ (1,0) [0|3] ""  MBMU,PC

BO_ 2332426072 S2A_SUMDATA5__24: 8 SBMU
 SG_ CRC_S2A_S5_24 : 0|8@1+ (1,0) [0|255] ""  MBMU,PC
 SG_ BAT_SOH_HVS_24 : 8|10@1+ (0.1,0) [0|102.3] "%"  MBMU,PC
 SG_ BAT_SOC_HVS_24 : 18|10@1+ (0.1,0) [0|102.3] "%"  MBMU,PC
 SG_ BAT_User_SOC_HVS_24 : 28|10@1+ (0.1,0) [0|102.3] "%"  MBMU,PC
 SG_ BAT_Cell_Max_SOC_HVS_24 : 38|10@1+ (0.1,0) [0|102.3] "%"  MBMU,PC
 SG_ BAT_Cell_Min_SOC_HVS_24 : 48|10@1+ (0.1,0) [0|102.3] "%"  MBMU,PC
 SG_ BAT_Cool_CellBalStat_24 : 61|1@1+ (1,0) [0|1] ""  MBMU,PC
 SG_ BAT_CorrectState_Require : 62|2@1+ (1,0) [0|3] ""  MBMU,PC

BO_ 2332426073 S2A_SUMDATA5__25: 8 SBMU
 SG_ CRC_S2A_S5_25 : 0|8@1+ (1,0) [0|255] ""  MBMU,PC
 SG_ BAT_SOH_HVS_25 : 8|10@1+ (0.1,0) [0|102.3] "%"  MBMU,PC
 SG_ BAT_SOC_HVS_25 : 18|10@1+ (0.1,0) [0|102.3] "%"  MBMU,PC
 SG_ BAT_User_SOC_HVS_25 : 28|10@1+ (0.1,0) [0|102.3] "%"  MBMU,PC
 SG_ BAT_Cell_Max_SOC_HVS_25 : 38|10@1+ (0.1,0) [0|102.3] "%"  MBMU,PC
 SG_ BAT_Cell_Min_SOC_HVS_25 : 48|10@1+ (0.1,0) [0|102.3] "%"  MBMU,PC
 SG_ BAT_Cool_CellBalStat_25 : 61|1@1+ (1,0) [0|1] ""  MBMU,PC
 SG_ BAT_CorrectState_Require : 62|2@1+ (1,0) [0|3] ""  MBMU,PC

BO_ 2332426074 S2A_SUMDATA5__26: 8 SBMU
 SG_ CRC_S2A_S5_26 : 0|8@1+ (1,0) [0|255] ""  MBMU,PC
 SG_ BAT_SOH_HVS_26 : 8|10@1+ (0.1,0) [0|102.3] "%"  MBMU,PC
 SG_ BAT_SOC_HVS_26 : 18|10@1+ (0.1,0) [0|102.3] "%"  MBMU,PC
 SG_ BAT_User_SOC_HVS_26 : 28|10@1+ (0.1,0) [0|102.3] "%"  MBMU,PC
 SG_ BAT_Cell_Max_SOC_HVS_26 : 38|10@1+ (0.1,0) [0|102.3] "%"  MBMU,PC
 SG_ BAT_Cell_Min_SOC_HVS_26 : 48|10@1+ (0.1,0) [0|102.3] "%"  MBMU,PC
 SG_ BAT_Cool_CellBalStat_26 : 61|1@1+ (1,0) [0|1] ""  MBMU,PC
 SG_ BAT_CorrectState_Require : 62|2@1+ (1,0) [0|3] ""  MBMU,PC

BO_ 2332426075 S2A_SUMDATA5__27: 8 SBMU
 SG_ CRC_S2A_S5_27 : 0|8@1+ (1,0) [0|255] ""  MBMU,PC
 SG_ BAT_SOH_HVS_27 : 8|10@1+ (0.1,0) [0|102.3] "%"  MBMU,PC
 SG_ BAT_SOC_HVS_27 : 18|10@1+ (0.1,0) [0|102.3] "%"  MBMU,PC
 SG_ BAT_User_SOC_HVS_27 : 28|10@1+ (0.1,0) [0|102.3] "%"  MBMU,PC
 SG_ BAT_Cell_Max_SOC_HVS_27 : 38|10@1+ (0.1,0) [0|102.3] "%"  MBMU,PC
 SG_ BAT_Cell_Min_SOC_HVS_27 : 48|10@1+ (0.1,0) [0|102.3] "%"  MBMU,PC
 SG_ BAT_Cool_CellBalStat_27 : 61|1@1+ (1,0) [0|1] ""  MBMU,PC
 SG_ BAT_CorrectState_Require : 62|2@1+ (1,0) [0|3] ""  MBMU,PC

BO_ 2332426076 S2A_SUMDATA5__28: 8 SBMU
 SG_ CRC_S2A_S5_28 : 0|8@1+ (1,0) [0|255] ""  MBMU,PC
 SG_ BAT_SOH_HVS_28 : 8|10@1+ (0.1,0) [0|102.3] "%"  MBMU,PC
 SG_ BAT_SOC_HVS_28 : 18|10@1+ (0.1,0) [0|102.3] "%"  MBMU,PC
 SG_ BAT_User_SOC_HVS_28 : 28|10@1+ (0.1,0) [0|102.3] "%"  MBMU,PC
 SG_ BAT_Cell_Max_SOC_HVS_28 : 38|10@1+ (0.1,0) [0|102.3] "%"  MBMU,PC
 SG_ BAT_Cell_Min_SOC_HVS_28 : 48|10@1+ (0.1,0) [0|102.3] "%"  MBMU,PC
 SG_ BAT_Cool_CellBalStat_28 : 61|1@1+ (1,0) [0|1] ""  MBMU,PC
 SG_ BAT_CorrectState_Require : 62|2@1+ (1,0) [0|3] ""  MBMU,PC

BO_ 2332426077 S2A_SUMDATA5__29: 8 SBMU
 SG_ CRC_S2A_S5_29 : 0|8@1+ (1,0) [0|255] ""  MBMU,PC
 SG_ BAT_SOH_HVS_29 : 8|10@1+ (0.1,0) [0|102.3] "%"  MBMU,PC
 SG_ BAT_SOC_HVS_29 : 18|10@1+ (0.1,0) [0|102.3] "%"  MBMU,PC
 SG_ BAT_User_SOC_HVS_29 : 28|10@1+ (0.1,0) [0|102.3] "%"  MBMU,PC
 SG_ BAT_Cell_Max_SOC_HVS_29 : 38|10@1+ (0.1,0) [0|102.3] "%"  MBMU,PC
 SG_ BAT_Cell_Min_SOC_HVS_29 : 48|10@1+ (0.1,0) [0|102.3] "%"  MBMU,PC
 SG_ BAT_Cool_CellBalStat_29 : 61|1@1+ (1,0) [0|1] ""  MBMU,PC
 SG_ BAT_CorrectState_Require : 62|2@1+ (1,0) [0|3] ""  MBMU,PC

BO_ 2332426078 S2A_SUMDATA5__30: 8 SBMU
 SG_ CRC_S2A_S5_30 : 0|8@1+ (1,0) [0|255] ""  MBMU,PC
 SG_ BAT_SOH_HVS_30 : 8|10@1+ (0.1,0) [0|102.3] "%"  MBMU,PC
 SG_ BAT_SOC_HVS_30 : 18|10@1+ (0.1,0) [0|102.3] "%"  MBMU,PC
 SG_ BAT_User_SOC_HVS_30 : 28|10@1+ (0.1,0) [0|102.3] "%"  MBMU,PC
 SG_ BAT_Cell_Max_SOC_HVS_30 : 38|10@1+ (0.1,0) [0|102.3] "%"  MBMU,PC
 SG_ BAT_Cell_Min_SOC_HVS_30 : 48|10@1+ (0.1,0) [0|102.3] "%"  MBMU,PC
 SG_ BAT_Cool_CellBalStat_30 : 61|1@1+ (1,0) [0|1] ""  MBMU,PC
 SG_ BAT_CorrectState_Require : 62|2@1+ (1,0) [0|3] ""  MBMU,PC

BO_ 2332426079 S2A_SUMDATA5__31: 8 SBMU
 SG_ CRC_S2A_S5_31 : 0|8@1+ (1,0) [0|255] ""  MBMU,PC
 SG_ BAT_SOH_HVS_31 : 8|10@1+ (0.1,0) [0|102.3] "%"  MBMU,PC
 SG_ BAT_SOC_HVS_31 : 18|10@1+ (0.1,0) [0|102.3] "%"  MBMU,PC
 SG_ BAT_User_SOC_HVS_31 : 28|10@1+ (0.1,0) [0|102.3] "%"  MBMU,PC
 SG_ BAT_Cell_Max_SOC_HVS_31 : 38|10@1+ (0.1,0) [0|102.3] "%"  MBMU,PC
 SG_ BAT_Cell_Min_SOC_HVS_31 : 48|10@1+ (0.1,0) [0|102.3] "%"  MBMU,PC
 SG_ BAT_Cool_CellBalStat_31 : 61|1@1+ (1,0) [0|1] ""  MBMU,PC
 SG_ BAT_CorrectState_Require : 62|2@1+ (1,0) [0|3] ""  MBMU,PC

BO_ 2332426080 S2A_SUMDATA5__32: 8 SBMU
 SG_ CRC_S2A_S5_32 : 0|8@1+ (1,0) [0|255] ""  MBMU,PC
 SG_ BAT_SOH_HVS_32 : 8|10@1+ (0.1,0) [0|102.3] "%"  MBMU,PC
 SG_ BAT_SOC_HVS_32 : 18|10@1+ (0.1,0) [0|102.3] "%"  MBMU,PC
 SG_ BAT_User_SOC_HVS_32 : 28|10@1+ (0.1,0) [0|102.3] "%"  MBMU,PC
 SG_ BAT_Cell_Max_SOC_HVS_32 : 38|10@1+ (0.1,0) [0|102.3] "%"  MBMU,PC
 SG_ BAT_Cell_Min_SOC_HVS_32 : 48|10@1+ (0.1,0) [0|102.3] "%"  MBMU,PC
 SG_ BAT_Cool_CellBalStat_32 : 61|1@1+ (1,0) [0|1] ""  MBMU,PC
 SG_ BAT_CorrectState_Require : 62|2@1+ (1,0) [0|3] ""  MBMU,PC

BO_ 2332426081 S2A_SUMDATA5__33: 8 SBMU
 SG_ CRC_S2A_S5_33 : 0|8@1+ (1,0) [0|255] ""  MBMU,PC
 SG_ BAT_SOH_HVS_33 : 8|10@1+ (0.1,0) [0|102.3] "%"  MBMU,PC
 SG_ BAT_SOC_HVS_33 : 18|10@1+ (0.1,0) [0|102.3] "%"  MBMU,PC
 SG_ BAT_User_SOC_HVS_33 : 28|10@1+ (0.1,0) [0|102.3] "%"  MBMU,PC
 SG_ BAT_Cell_Max_SOC_HVS_33 : 38|10@1+ (0.1,0) [0|102.3] "%"  MBMU,PC
 SG_ BAT_Cell_Min_SOC_HVS_33 : 48|10@1+ (0.1,0) [0|102.3] "%"  MBMU,PC
 SG_ BAT_Cool_CellBalStat_33 : 61|1@1+ (1,0) [0|1] ""  MBMU,PC
 SG_ BAT_CorrectState_Require : 62|2@1+ (1,0) [0|3] ""  MBMU,PC

BO_ 2332426082 S2A_SUMDATA5__34: 8 SBMU
 SG_ CRC_S2A_S5_34 : 0|8@1+ (1,0) [0|255] ""  MBMU,PC
 SG_ BAT_SOH_HVS_34 : 8|10@1+ (0.1,0) [0|102.3] "%"  MBMU,PC
 SG_ BAT_SOC_HVS_34 : 18|10@1+ (0.1,0) [0|102.3] "%"  MBMU,PC
 SG_ BAT_User_SOC_HVS_34 : 28|10@1+ (0.1,0) [0|102.3] "%"  MBMU,PC
 SG_ BAT_Cell_Max_SOC_HVS_34 : 38|10@1+ (0.1,0) [0|102.3] "%"  MBMU,PC
 SG_ BAT_Cell_Min_SOC_HVS_34 : 48|10@1+ (0.1,0) [0|102.3] "%"  MBMU,PC
 SG_ BAT_Cool_CellBalStat_34 : 61|1@1+ (1,0) [0|1] ""  MBMU,PC
 SG_ BAT_CorrectState_Require : 62|2@1+ (1,0) [0|3] ""  MBMU,PC

BO_ 2332426083 S2A_SUMDATA5__35: 8 SBMU
 SG_ CRC_S2A_S5_35 : 0|8@1+ (1,0) [0|255] ""  MBMU,PC
 SG_ BAT_SOH_HVS_35 : 8|10@1+ (0.1,0) [0|102.3] "%"  MBMU,PC
 SG_ BAT_SOC_HVS_35 : 18|10@1+ (0.1,0) [0|102.3] "%"  MBMU,PC
 SG_ BAT_User_SOC_HVS_35 : 28|10@1+ (0.1,0) [0|102.3] "%"  MBMU,PC
 SG_ BAT_Cell_Max_SOC_HVS_35 : 38|10@1+ (0.1,0) [0|102.3] "%"  MBMU,PC
 SG_ BAT_Cell_Min_SOC_HVS_35 : 48|10@1+ (0.1,0) [0|102.3] "%"  MBMU,PC
 SG_ BAT_Cool_CellBalStat_35 : 61|1@1+ (1,0) [0|1] ""  MBMU,PC
 SG_ BAT_CorrectState_Require : 62|2@1+ (1,0) [0|3] ""  MBMU,PC

BO_ 2332426084 S2A_SUMDATA5__36: 8 SBMU
 SG_ CRC_S2A_S5_36 : 0|8@1+ (1,0) [0|255] ""  MBMU,PC
 SG_ BAT_SOH_HVS_36 : 8|10@1+ (0.1,0) [0|102.3] "%"  MBMU,PC
 SG_ BAT_SOC_HVS_36 : 18|10@1+ (0.1,0) [0|102.3] "%"  MBMU,PC
 SG_ BAT_User_SOC_HVS_36 : 28|10@1+ (0.1,0) [0|102.3] "%"  MBMU,PC
 SG_ BAT_Cell_Max_SOC_HVS_36 : 38|10@1+ (0.1,0) [0|102.3] "%"  MBMU,PC
 SG_ BAT_Cell_Min_SOC_HVS_36 : 48|10@1+ (0.1,0) [0|102.3] "%"  MBMU,PC
 SG_ BAT_Cool_CellBalStat_36 : 61|1@1+ (1,0) [0|1] ""  MBMU,PC
 SG_ BAT_CorrectState_Require : 62|2@1+ (1,0) [0|3] ""  MBMU,PC

BO_ 2332426085 S2A_SUMDATA5__37: 8 SBMU
 SG_ CRC_S2A_S5_37 : 0|8@1+ (1,0) [0|255] ""  MBMU,PC
 SG_ BAT_SOH_HVS_37 : 8|10@1+ (0.1,0) [0|102.3] "%"  MBMU,PC
 SG_ BAT_SOC_HVS_37 : 18|10@1+ (0.1,0) [0|102.3] "%"  MBMU,PC
 SG_ BAT_User_SOC_HVS_37 : 28|10@1+ (0.1,0) [0|102.3] "%"  MBMU,PC
 SG_ BAT_Cell_Max_SOC_HVS_37 : 38|10@1+ (0.1,0) [0|102.3] "%"  MBMU,PC
 SG_ BAT_Cell_Min_SOC_HVS_37 : 48|10@1+ (0.1,0) [0|102.3] "%"  MBMU,PC
 SG_ BAT_Cool_CellBalStat_37 : 61|1@1+ (1,0) [0|1] ""  MBMU,PC
 SG_ BAT_CorrectState_Require : 62|2@1+ (1,0) [0|3] ""  MBMU,PC

BO_ 2332426086 S2A_SUMDATA5__38: 8 SBMU
 SG_ CRC_S2A_S5_38 : 0|8@1+ (1,0) [0|255] ""  MBMU,PC
 SG_ BAT_SOH_HVS_38 : 8|10@1+ (0.1,0) [0|102.3] "%"  MBMU,PC
 SG_ BAT_SOC_HVS_38 : 18|10@1+ (0.1,0) [0|102.3] "%"  MBMU,PC
 SG_ BAT_User_SOC_HVS_38 : 28|10@1+ (0.1,0) [0|102.3] "%"  MBMU,PC
 SG_ BAT_Cell_Max_SOC_HVS_38 : 38|10@1+ (0.1,0) [0|102.3] "%"  MBMU,PC
 SG_ BAT_Cell_Min_SOC_HVS_38 : 48|10@1+ (0.1,0) [0|102.3] "%"  MBMU,PC
 SG_ BAT_Cool_CellBalStat_38 : 61|1@1+ (1,0) [0|1] ""  MBMU,PC
 SG_ BAT_CorrectState_Require : 62|2@1+ (1,0) [0|3] ""  MBMU,PC

BO_ 2332426087 S2A_SUMDATA5__39: 8 SBMU
 SG_ CRC_S2A_S5_39 : 0|8@1+ (1,0) [0|255] ""  MBMU,PC
 SG_ BAT_SOH_HVS_39 : 8|10@1+ (0.1,0) [0|102.3] "%"  MBMU,PC
 SG_ BAT_SOC_HVS_39 : 18|10@1+ (0.1,0) [0|102.3] "%"  MBMU,PC
 SG_ BAT_User_SOC_HVS_39 : 28|10@1+ (0.1,0) [0|102.3] "%"  MBMU,PC
 SG_ BAT_Cell_Max_SOC_HVS_39 : 38|10@1+ (0.1,0) [0|102.3] "%"  MBMU,PC
 SG_ BAT_Cell_Min_SOC_HVS_39 : 48|10@1+ (0.1,0) [0|102.3] "%"  MBMU,PC
 SG_ BAT_Cool_CellBalStat_39 : 61|1@1+ (1,0) [0|1] ""  MBMU,PC
 SG_ BAT_CorrectState_Require : 62|2@1+ (1,0) [0|3] ""  MBMU,PC

BO_ 2332426088 S2A_SUMDATA5__40: 8 SBMU
 SG_ CRC_S2A_S5_40 : 0|8@1+ (1,0) [0|255] ""  MBMU,PC
 SG_ BAT_SOH_HVS_40 : 8|10@1+ (0.1,0) [0|102.3] "%"  MBMU,PC
 SG_ BAT_SOC_HVS_40 : 18|10@1+ (0.1,0) [0|102.3] "%"  MBMU,PC
 SG_ BAT_User_SOC_HVS_40 : 28|10@1+ (0.1,0) [0|102.3] "%"  MBMU,PC
 SG_ BAT_Cell_Max_SOC_HVS_40 : 38|10@1+ (0.1,0) [0|102.3] "%"  MBMU,PC
 SG_ BAT_Cell_Min_SOC_HVS_40 : 48|10@1+ (0.1,0) [0|102.3] "%"  MBMU,PC
 SG_ BAT_Cool_CellBalStat_40 : 61|1@1+ (1,0) [0|1] ""  MBMU,PC
 SG_ BAT_CorrectState_Require : 62|2@1+ (1,0) [0|3] ""  MBMU,PC

BO_ 2332426089 S2A_SUMDATA5__41: 8 SBMU
 SG_ CRC_S2A_S5_41 : 0|8@1+ (1,0) [0|255] ""  MBMU,PC
 SG_ BAT_SOH_HVS_41 : 8|10@1+ (0.1,0) [0|102.3] "%"  MBMU,PC
 SG_ BAT_SOC_HVS_41 : 18|10@1+ (0.1,0) [0|102.3] "%"  MBMU,PC
 SG_ BAT_User_SOC_HVS_41 : 28|10@1+ (0.1,0) [0|102.3] "%"  MBMU,PC
 SG_ BAT_Cell_Max_SOC_HVS_41 : 38|10@1+ (0.1,0) [0|102.3] "%"  MBMU,PC
 SG_ BAT_Cell_Min_SOC_HVS_41 : 48|10@1+ (0.1,0) [0|102.3] "%"  MBMU,PC
 SG_ BAT_Cool_CellBalStat_41 : 61|1@1+ (1,0) [0|1] ""  MBMU,PC
 SG_ BAT_CorrectState_Require : 62|2@1+ (1,0) [0|3] ""  MBMU,PC

BO_ 2332426090 S2A_SUMDATA5__42: 8 SBMU
 SG_ CRC_S2A_S5_42 : 0|8@1+ (1,0) [0|255] ""  MBMU,PC
 SG_ BAT_SOH_HVS_42 : 8|10@1+ (0.1,0) [0|102.3] "%"  MBMU,PC
 SG_ BAT_SOC_HVS_42 : 18|10@1+ (0.1,0) [0|102.3] "%"  MBMU,PC
 SG_ BAT_User_SOC_HVS_42 : 28|10@1+ (0.1,0) [0|102.3] "%"  MBMU,PC
 SG_ BAT_Cell_Max_SOC_HVS_42 : 38|10@1+ (0.1,0) [0|102.3] "%"  MBMU,PC
 SG_ BAT_Cell_Min_SOC_HVS_42 : 48|10@1+ (0.1,0) [0|102.3] "%"  MBMU,PC
 SG_ BAT_Cool_CellBalStat_42 : 61|1@1+ (1,0) [0|1] ""  MBMU,PC
 SG_ BAT_CorrectState_Require : 62|2@1+ (1,0) [0|3] ""  MBMU,PC

BO_ 2332426091 S2A_SUMDATA5__43: 8 SBMU
 SG_ CRC_S2A_S5_43 : 0|8@1+ (1,0) [0|255] ""  MBMU,PC
 SG_ BAT_SOH_HVS_43 : 8|10@1+ (0.1,0) [0|102.3] "%"  MBMU,PC
 SG_ BAT_SOC_HVS_43 : 18|10@1+ (0.1,0) [0|102.3] "%"  MBMU,PC
 SG_ BAT_User_SOC_HVS_43 : 28|10@1+ (0.1,0) [0|102.3] "%"  MBMU,PC
 SG_ BAT_Cell_Max_SOC_HVS_43 : 38|10@1+ (0.1,0) [0|102.3] "%"  MBMU,PC
 SG_ BAT_Cell_Min_SOC_HVS_43 : 48|10@1+ (0.1,0) [0|102.3] "%"  MBMU,PC
 SG_ BAT_Cool_CellBalStat_43 : 61|1@1+ (1,0) [0|1] ""  MBMU,PC
 SG_ BAT_CorrectState_Require : 62|2@1+ (1,0) [0|3] ""  MBMU,PC

BO_ 2332426092 S2A_SUMDATA5__44: 8 SBMU
 SG_ CRC_S2A_S5_44 : 0|8@1+ (1,0) [0|255] ""  MBMU,PC
 SG_ BAT_SOH_HVS_44 : 8|10@1+ (0.1,0) [0|102.3] "%"  MBMU,PC
 SG_ BAT_SOC_HVS_44 : 18|10@1+ (0.1,0) [0|102.3] "%"  MBMU,PC
 SG_ BAT_User_SOC_HVS_44 : 28|10@1+ (0.1,0) [0|102.3] "%"  MBMU,PC
 SG_ BAT_Cell_Max_SOC_HVS_44 : 38|10@1+ (0.1,0) [0|102.3] "%"  MBMU,PC
 SG_ BAT_Cell_Min_SOC_HVS_44 : 48|10@1+ (0.1,0) [0|102.3] "%"  MBMU,PC
 SG_ BAT_Cool_CellBalStat_44 : 61|1@1+ (1,0) [0|1] ""  MBMU,PC
 SG_ BAT_CorrectState_Require : 62|2@1+ (1,0) [0|3] ""  MBMU,PC

BO_ 2332426093 S2A_SUMDATA5__45: 8 SBMU
 SG_ CRC_S2A_S5_45 : 0|8@1+ (1,0) [0|255] ""  MBMU,PC
 SG_ BAT_SOH_HVS_45 : 8|10@1+ (0.1,0) [0|102.3] "%"  MBMU,PC
 SG_ BAT_SOC_HVS_45 : 18|10@1+ (0.1,0) [0|102.3] "%"  MBMU,PC
 SG_ BAT_User_SOC_HVS_45 : 28|10@1+ (0.1,0) [0|102.3] "%"  MBMU,PC
 SG_ BAT_Cell_Max_SOC_HVS_45 : 38|10@1+ (0.1,0) [0|102.3] "%"  MBMU,PC
 SG_ BAT_Cell_Min_SOC_HVS_45 : 48|10@1+ (0.1,0) [0|102.3] "%"  MBMU,PC
 SG_ BAT_Cool_CellBalStat_45 : 61|1@1+ (1,0) [0|1] ""  MBMU,PC
 SG_ BAT_CorrectState_Require : 62|2@1+ (1,0) [0|3] ""  MBMU,PC

BO_ 2332426094 S2A_SUMDATA5__46: 8 SBMU
 SG_ CRC_S2A_S5_46 : 0|8@1+ (1,0) [0|255] ""  MBMU,PC
 SG_ BAT_SOH_HVS_46 : 8|10@1+ (0.1,0) [0|102.3] "%"  MBMU,PC
 SG_ BAT_SOC_HVS_46 : 18|10@1+ (0.1,0) [0|102.3] "%"  MBMU,PC
 SG_ BAT_User_SOC_HVS_46 : 28|10@1+ (0.1,0) [0|102.3] "%"  MBMU,PC
 SG_ BAT_Cell_Max_SOC_HVS_46 : 38|10@1+ (0.1,0) [0|102.3] "%"  MBMU,PC
 SG_ BAT_Cell_Min_SOC_HVS_46 : 48|10@1+ (0.1,0) [0|102.3] "%"  MBMU,PC
 SG_ BAT_Cool_CellBalStat_46 : 61|1@1+ (1,0) [0|1] ""  MBMU,PC
 SG_ BAT_CorrectState_Require : 62|2@1+ (1,0) [0|3] ""  MBMU,PC

BO_ 2332426095 S2A_SUMDATA5__47: 8 SBMU
 SG_ CRC_S2A_S5_47 : 0|8@1+ (1,0) [0|255] ""  MBMU,PC
 SG_ BAT_SOH_HVS_47 : 8|10@1+ (0.1,0) [0|102.3] "%"  MBMU,PC
 SG_ BAT_SOC_HVS_47 : 18|10@1+ (0.1,0) [0|102.3] "%"  MBMU,PC
 SG_ BAT_User_SOC_HVS_47 : 28|10@1+ (0.1,0) [0|102.3] "%"  MBMU,PC
 SG_ BAT_Cell_Max_SOC_HVS_47 : 38|10@1+ (0.1,0) [0|102.3] "%"  MBMU,PC
 SG_ BAT_Cell_Min_SOC_HVS_47 : 48|10@1+ (0.1,0) [0|102.3] "%"  MBMU,PC
 SG_ BAT_Cool_CellBalStat_47 : 61|1@1+ (1,0) [0|1] ""  MBMU,PC
 SG_ BAT_CorrectState_Require : 62|2@1+ (1,0) [0|3] ""  MBMU,PC

BO_ 2332426096 S2A_SUMDATA5__48: 8 SBMU
 SG_ CRC_S2A_S5_48 : 0|8@1+ (1,0) [0|255] ""  MBMU,PC
 SG_ BAT_SOH_HVS_48 : 8|10@1+ (0.1,0) [0|102.3] "%"  MBMU,PC
 SG_ BAT_SOC_HVS_48 : 18|10@1+ (0.1,0) [0|102.3] "%"  MBMU,PC
 SG_ BAT_User_SOC_HVS_48 : 28|10@1+ (0.1,0) [0|102.3] "%"  MBMU,PC
 SG_ BAT_Cell_Max_SOC_HVS_48 : 38|10@1+ (0.1,0) [0|102.3] "%"  MBMU,PC
 SG_ BAT_Cell_Min_SOC_HVS_48 : 48|10@1+ (0.1,0) [0|102.3] "%"  MBMU,PC
 SG_ BAT_Cool_CellBalStat_48 : 61|1@1+ (1,0) [0|1] ""  MBMU,PC
 SG_ BAT_CorrectState_Require : 62|2@1+ (1,0) [0|3] ""  MBMU,PC

BO_ 2332426097 S2A_SUMDATA5__49: 8 SBMU
 SG_ CRC_S2A_S5_49 : 0|8@1+ (1,0) [0|255] ""  MBMU,PC
 SG_ BAT_SOH_HVS_49 : 8|10@1+ (0.1,0) [0|102.3] "%"  MBMU,PC
 SG_ BAT_SOC_HVS_49 : 18|10@1+ (0.1,0) [0|102.3] "%"  MBMU,PC
 SG_ BAT_User_SOC_HVS_49 : 28|10@1+ (0.1,0) [0|102.3] "%"  MBMU,PC
 SG_ BAT_Cell_Max_SOC_HVS_49 : 38|10@1+ (0.1,0) [0|102.3] "%"  MBMU,PC
 SG_ BAT_Cell_Min_SOC_HVS_49 : 48|10@1+ (0.1,0) [0|102.3] "%"  MBMU,PC
 SG_ BAT_Cool_CellBalStat_49 : 61|1@1+ (1,0) [0|1] ""  MBMU,PC
 SG_ BAT_CorrectState_Require : 62|2@1+ (1,0) [0|3] ""  MBMU,PC

BO_ 2332426098 S2A_SUMDATA5__50: 8 SBMU
 SG_ CRC_S2A_S5_50 : 0|8@1+ (1,0) [0|255] ""  MBMU,PC
 SG_ BAT_SOH_HVS_50 : 8|10@1+ (0.1,0) [0|102.3] "%"  MBMU,PC
 SG_ BAT_SOC_HVS_50 : 18|10@1+ (0.1,0) [0|102.3] "%"  MBMU,PC
 SG_ BAT_User_SOC_HVS_50 : 28|10@1+ (0.1,0) [0|102.3] "%"  MBMU,PC
 SG_ BAT_Cell_Max_SOC_HVS_50 : 38|10@1+ (0.1,0) [0|102.3] "%"  MBMU,PC
 SG_ BAT_Cell_Min_SOC_HVS_50 : 48|10@1+ (0.1,0) [0|102.3] "%"  MBMU,PC
 SG_ BAT_Cool_CellBalStat_50 : 61|1@1+ (1,0) [0|1] ""  MBMU,PC
 SG_ BAT_CorrectState_Require : 62|2@1+ (1,0) [0|3] ""  MBMU,PC

BO_ 2332426099 S2A_SUMDATA5__51: 8 SBMU
 SG_ CRC_S2A_S5_51 : 0|8@1+ (1,0) [0|255] ""  MBMU,PC
 SG_ BAT_SOH_HVS_51 : 8|10@1+ (0.1,0) [0|102.3] "%"  MBMU,PC
 SG_ BAT_SOC_HVS_51 : 18|10@1+ (0.1,0) [0|102.3] "%"  MBMU,PC
 SG_ BAT_User_SOC_HVS_51 : 28|10@1+ (0.1,0) [0|102.3] "%"  MBMU,PC
 SG_ BAT_Cell_Max_SOC_HVS_51 : 38|10@1+ (0.1,0) [0|102.3] "%"  MBMU,PC
 SG_ BAT_Cell_Min_SOC_HVS_51 : 48|10@1+ (0.1,0) [0|102.3] "%"  MBMU,PC
 SG_ BAT_Cool_CellBalStat_51 : 61|1@1+ (1,0) [0|1] ""  MBMU,PC
 SG_ BAT_CorrectState_Require : 62|2@1+ (1,0) [0|3] ""  MBMU,PC

BO_ 2332426100 S2A_SUMDATA5__52: 8 SBMU
 SG_ CRC_S2A_S5_52 : 0|8@1+ (1,0) [0|255] ""  MBMU,PC
 SG_ BAT_SOH_HVS_52 : 8|10@1+ (0.1,0) [0|102.3] "%"  MBMU,PC
 SG_ BAT_SOC_HVS_52 : 18|10@1+ (0.1,0) [0|102.3] "%"  MBMU,PC
 SG_ BAT_User_SOC_HVS_52 : 28|10@1+ (0.1,0) [0|102.3] "%"  MBMU,PC
 SG_ BAT_Cell_Max_SOC_HVS_52 : 38|10@1+ (0.1,0) [0|102.3] "%"  MBMU,PC
 SG_ BAT_Cell_Min_SOC_HVS_52 : 48|10@1+ (0.1,0) [0|102.3] "%"  MBMU,PC
 SG_ BAT_Cool_CellBalStat_52 : 61|1@1+ (1,0) [0|1] ""  MBMU,PC
 SG_ BAT_CorrectState_Require : 62|2@1+ (1,0) [0|3] ""  MBMU,PC

BO_ 2332426101 S2A_SUMDATA5__53: 8 SBMU
 SG_ CRC_S2A_S5_53 : 0|8@1+ (1,0) [0|255] ""  MBMU,PC
 SG_ BAT_SOH_HVS_53 : 8|10@1+ (0.1,0) [0|102.3] "%"  MBMU,PC
 SG_ BAT_SOC_HVS_53 : 18|10@1+ (0.1,0) [0|102.3] "%"  MBMU,PC
 SG_ BAT_User_SOC_HVS_53 : 28|10@1+ (0.1,0) [0|102.3] "%"  MBMU,PC
 SG_ BAT_Cell_Max_SOC_HVS_53 : 38|10@1+ (0.1,0) [0|102.3] "%"  MBMU,PC
 SG_ BAT_Cell_Min_SOC_HVS_53 : 48|10@1+ (0.1,0) [0|102.3] "%"  MBMU,PC
 SG_ BAT_Cool_CellBalStat_53 : 61|1@1+ (1,0) [0|1] ""  MBMU,PC
 SG_ BAT_CorrectState_Require : 62|2@1+ (1,0) [0|3] ""  MBMU,PC

BO_ 2332426102 S2A_SUMDATA5__54: 8 SBMU
 SG_ CRC_S2A_S5_54 : 0|8@1+ (1,0) [0|255] ""  MBMU,PC
 SG_ BAT_SOH_HVS_54 : 8|10@1+ (0.1,0) [0|102.3] "%"  MBMU,PC
 SG_ BAT_SOC_HVS_54 : 18|10@1+ (0.1,0) [0|102.3] "%"  MBMU,PC
 SG_ BAT_User_SOC_HVS_54 : 28|10@1+ (0.1,0) [0|102.3] "%"  MBMU,PC
 SG_ BAT_Cell_Max_SOC_HVS_54 : 38|10@1+ (0.1,0) [0|102.3] "%"  MBMU,PC
 SG_ BAT_Cell_Min_SOC_HVS_54 : 48|10@1+ (0.1,0) [0|102.3] "%"  MBMU,PC
 SG_ BAT_Cool_CellBalStat_54 : 61|1@1+ (1,0) [0|1] ""  MBMU,PC
 SG_ BAT_CorrectState_Require : 62|2@1+ (1,0) [0|3] ""  MBMU,PC

BO_ 2332426103 S2A_SUMDATA5__55: 8 SBMU
 SG_ CRC_S2A_S5_55 : 0|8@1+ (1,0) [0|255] ""  MBMU,PC
 SG_ BAT_SOH_HVS_55 : 8|10@1+ (0.1,0) [0|102.3] "%"  MBMU,PC
 SG_ BAT_SOC_HVS_55 : 18|10@1+ (0.1,0) [0|102.3] "%"  MBMU,PC
 SG_ BAT_User_SOC_HVS_55 : 28|10@1+ (0.1,0) [0|102.3] "%"  MBMU,PC
 SG_ BAT_Cell_Max_SOC_HVS_55 : 38|10@1+ (0.1,0) [0|102.3] "%"  MBMU,PC
 SG_ BAT_Cell_Min_SOC_HVS_55 : 48|10@1+ (0.1,0) [0|102.3] "%"  MBMU,PC
 SG_ BAT_Cool_CellBalStat_55 : 61|1@1+ (1,0) [0|1] ""  MBMU,PC
 SG_ BAT_CorrectState_Require : 62|2@1+ (1,0) [0|3] ""  MBMU,PC

BO_ 2332426104 S2A_SUMDATA5__56: 8 SBMU
 SG_ CRC_S2A_S5_56 : 0|8@1+ (1,0) [0|255] ""  MBMU,PC
 SG_ BAT_SOH_HVS_56 : 8|10@1+ (0.1,0) [0|102.3] "%"  MBMU,PC
 SG_ BAT_SOC_HVS_56 : 18|10@1+ (0.1,0) [0|102.3] "%"  MBMU,PC
 SG_ BAT_User_SOC_HVS_56 : 28|10@1+ (0.1,0) [0|102.3] "%"  MBMU,PC
 SG_ BAT_Cell_Max_SOC_HVS_56 : 38|10@1+ (0.1,0) [0|102.3] "%"  MBMU,PC
 SG_ BAT_Cell_Min_SOC_HVS_56 : 48|10@1+ (0.1,0) [0|102.3] "%"  MBMU,PC
 SG_ BAT_Cool_CellBalStat_56 : 61|1@1+ (1,0) [0|1] ""  MBMU,PC
 SG_ BAT_CorrectState_Require : 62|2@1+ (1,0) [0|3] ""  MBMU,PC

BO_ 2332426105 S2A_SUMDATA5__57: 8 SBMU
 SG_ CRC_S2A_S5_57 : 0|8@1+ (1,0) [0|255] ""  MBMU,PC
 SG_ BAT_SOH_HVS_57 : 8|10@1+ (0.1,0) [0|102.3] "%"  MBMU,PC
 SG_ BAT_SOC_HVS_57 : 18|10@1+ (0.1,0) [0|102.3] "%"  MBMU,PC
 SG_ BAT_User_SOC_HVS_57 : 28|10@1+ (0.1,0) [0|102.3] "%"  MBMU,PC
 SG_ BAT_Cell_Max_SOC_HVS_57 : 38|10@1+ (0.1,0) [0|102.3] "%"  MBMU,PC
 SG_ BAT_Cell_Min_SOC_HVS_57 : 48|10@1+ (0.1,0) [0|102.3] "%"  MBMU,PC
 SG_ BAT_Cool_CellBalStat_57 : 61|1@1+ (1,0) [0|1] ""  MBMU,PC
 SG_ BAT_CorrectState_Require : 62|2@1+ (1,0) [0|3] ""  MBMU,PC

BO_ 2332426106 S2A_SUMDATA5__58: 8 SBMU
 SG_ CRC_S2A_S5_58 : 0|8@1+ (1,0) [0|255] ""  MBMU,PC
 SG_ BAT_SOH_HVS_58 : 8|10@1+ (0.1,0) [0|102.3] "%"  MBMU,PC
 SG_ BAT_SOC_HVS_58 : 18|10@1+ (0.1,0) [0|102.3] "%"  MBMU,PC
 SG_ BAT_User_SOC_HVS_58 : 28|10@1+ (0.1,0) [0|102.3] "%"  MBMU,PC
 SG_ BAT_Cell_Max_SOC_HVS_58 : 38|10@1+ (0.1,0) [0|102.3] "%"  MBMU,PC
 SG_ BAT_Cell_Min_SOC_HVS_58 : 48|10@1+ (0.1,0) [0|102.3] "%"  MBMU,PC
 SG_ BAT_Cool_CellBalStat_58 : 61|1@1+ (1,0) [0|1] ""  MBMU,PC
 SG_ BAT_CorrectState_Require : 62|2@1+ (1,0) [0|3] ""  MBMU,PC

BO_ 2332426107 S2A_SUMDATA5__59: 8 SBMU
 SG_ CRC_S2A_S5_59 : 0|8@1+ (1,0) [0|255] ""  MBMU,PC
 SG_ BAT_SOH_HVS_59 : 8|10@1+ (0.1,0) [0|102.3] "%"  MBMU,PC
 SG_ BAT_SOC_HVS_59 : 18|10@1+ (0.1,0) [0|102.3] "%"  MBMU,PC
 SG_ BAT_User_SOC_HVS_59 : 28|10@1+ (0.1,0) [0|102.3] "%"  MBMU,PC
 SG_ BAT_Cell_Max_SOC_HVS_59 : 38|10@1+ (0.1,0) [0|102.3] "%"  MBMU,PC
 SG_ BAT_Cell_Min_SOC_HVS_59 : 48|10@1+ (0.1,0) [0|102.3] "%"  MBMU,PC
 SG_ BAT_Cool_CellBalStat_59 : 61|1@1+ (1,0) [0|1] ""  MBMU,PC
 SG_ BAT_CorrectState_Require : 62|2@1+ (1,0) [0|3] ""  MBMU,PC

BO_ 2332426108 S2A_SUMDATA5__60: 8 SBMU
 SG_ CRC_S2A_S5_60 : 0|8@1+ (1,0) [0|255] ""  MBMU,PC
 SG_ BAT_SOH_HVS_60 : 8|10@1+ (0.1,0) [0|102.3] "%"  MBMU,PC
 SG_ BAT_SOC_HVS_60 : 18|10@1+ (0.1,0) [0|102.3] "%"  MBMU,PC
 SG_ BAT_User_SOC_HVS_60 : 28|10@1+ (0.1,0) [0|102.3] "%"  MBMU,PC
 SG_ BAT_Cell_Max_SOC_HVS_60 : 38|10@1+ (0.1,0) [0|102.3] "%"  MBMU,PC
 SG_ BAT_Cell_Min_SOC_HVS_60 : 48|10@1+ (0.1,0) [0|102.3] "%"  MBMU,PC
 SG_ BAT_Cool_CellBalStat_60 : 61|1@1+ (1,0) [0|1] ""  MBMU,PC
 SG_ BAT_CorrectState_Require : 62|2@1+ (1,0) [0|3] ""  MBMU,PC

BO_ 2332426109 S2A_SUMDATA5__61: 8 SBMU
 SG_ CRC_S2A_S5_61 : 0|8@1+ (1,0) [0|255] ""  MBMU,PC
 SG_ BAT_SOH_HVS_61 : 8|10@1+ (0.1,0) [0|102.3] "%"  MBMU,PC
 SG_ BAT_SOC_HVS_61 : 18|10@1+ (0.1,0) [0|102.3] "%"  MBMU,PC
 SG_ BAT_User_SOC_HVS_61 : 28|10@1+ (0.1,0) [0|102.3] "%"  MBMU,PC
 SG_ BAT_Cell_Max_SOC_HVS_61 : 38|10@1+ (0.1,0) [0|102.3] "%"  MBMU,PC
 SG_ BAT_Cell_Min_SOC_HVS_61 : 48|10@1+ (0.1,0) [0|102.3] "%"  MBMU,PC
 SG_ BAT_Cool_CellBalStat_61 : 61|1@1+ (1,0) [0|1] ""  MBMU,PC
 SG_ BAT_CorrectState_Require : 62|2@1+ (1,0) [0|3] ""  MBMU,PC

BO_ 2332426110 S2A_SUMDATA5__62: 8 SBMU
 SG_ CRC_S2A_S5_62 : 0|8@1+ (1,0) [0|255] ""  MBMU,PC
 SG_ BAT_SOH_HVS_62 : 8|10@1+ (0.1,0) [0|102.3] "%"  MBMU,PC
 SG_ BAT_SOC_HVS_62 : 18|10@1+ (0.1,0) [0|102.3] "%"  MBMU,PC
 SG_ BAT_User_SOC_HVS_62 : 28|10@1+ (0.1,0) [0|102.3] "%"  MBMU,PC
 SG_ BAT_Cell_Max_SOC_HVS_62 : 38|10@1+ (0.1,0) [0|102.3] "%"  MBMU,PC
 SG_ BAT_Cell_Min_SOC_HVS_62 : 48|10@1+ (0.1,0) [0|102.3] "%"  MBMU,PC
 SG_ BAT_Cool_CellBalStat_62 : 61|1@1+ (1,0) [0|1] ""  MBMU,PC
 SG_ BAT_CorrectState_Require : 62|2@1+ (1,0) [0|3] ""  MBMU,PC

BO_ 2332426111 S2A_SUMDATA5__63: 8 SBMU
 SG_ CRC_S2A_S5_63 : 0|8@1+ (1,0) [0|255] ""  MBMU,PC
 SG_ BAT_SOH_HVS_63 : 8|10@1+ (0.1,0) [0|102.3] "%"  MBMU,PC
 SG_ BAT_SOC_HVS_63 : 18|10@1+ (0.1,0) [0|102.3] "%"  MBMU,PC
 SG_ BAT_User_SOC_HVS_63 : 28|10@1+ (0.1,0) [0|102.3] "%"  MBMU,PC
 SG_ BAT_Cell_Max_SOC_HVS_63 : 38|10@1+ (0.1,0) [0|102.3] "%"  MBMU,PC
 SG_ BAT_Cell_Min_SOC_HVS_63 : 48|10@1+ (0.1,0) [0|102.3] "%"  MBMU,PC
 SG_ BAT_Cool_CellBalStat_63 : 61|1@1+ (1,0) [0|1] ""  MBMU,PC
 SG_ BAT_CorrectState_Require : 62|2@1+ (1,0) [0|3] ""  MBMU,PC

BO_ 2332491585 S2A_SUMDATA6__01: 8 SBMU
 SG_ CRC_S2A_S6_01 : 0|8@1+ (1,0) [0|255] ""  MBMU,PC
 SG_ SBMU_Evn_T1_01 : 8|8@1+ (1,-50) [-50|205] "℃"  MBMU,PC
 SG_ SBMU_Evn_T2_01 : 16|8@1+ (1,-50) [-50|205] "℃"  MBMU,PC
 SG_ SBMU_Evn_T3_01 : 24|8@1+ (1,-50) [-50|205] "℃"  MBMU,PC
 SG_ S2A_STofCSCAutoCoding_01 : 36|4@1+ (1,0) [0|15] ""  MBMU,PC

BO_ 2332491586 S2A_SUMDATA6__02: 8 SBMU
 SG_ CRC_S2A_S6_02 : 0|8@1+ (1,0) [0|255] ""  MBMU,PC
 SG_ SBMU_Evn_T1_02 : 8|8@1+ (1,-50) [-50|205] "℃"  MBMU,PC
 SG_ SBMU_Evn_T2_02 : 16|8@1+ (1,-50) [-50|205] "℃"  MBMU,PC
 SG_ SBMU_Evn_T3_02 : 24|8@1+ (1,-50) [-50|205] "℃"  MBMU,PC
 SG_ S2A_STofCSCAutoCoding_02 : 36|4@1+ (1,0) [0|15] ""  MBMU,PC

BO_ 2332491587 S2A_SUMDATA6__03: 8 SBMU
 SG_ CRC_S2A_S6_03 : 0|8@1+ (1,0) [0|255] ""  MBMU,PC
 SG_ SBMU_Evn_T1_03 : 8|8@1+ (1,-50) [-50|205] "℃"  MBMU,PC
 SG_ SBMU_Evn_T2_03 : 16|8@1+ (1,-50) [-50|205] "℃"  MBMU,PC
 SG_ SBMU_Evn_T3_03 : 24|8@1+ (1,-50) [-50|205] "℃"  MBMU,PC
 SG_ S2A_STofCSCAutoCoding_03 : 36|4@1+ (1,0) [0|15] ""  MBMU,PC

BO_ 2332491588 S2A_SUMDATA6__04: 8 SBMU
 SG_ CRC_S2A_S6_04 : 0|8@1+ (1,0) [0|255] ""  MBMU,PC
 SG_ SBMU_Evn_T1_04 : 8|8@1+ (1,-50) [-50|205] "℃"  MBMU,PC
 SG_ SBMU_Evn_T2_04 : 16|8@1+ (1,-50) [-50|205] "℃"  MBMU,PC
 SG_ SBMU_Evn_T3_04 : 24|8@1+ (1,-50) [-50|205] "℃"  MBMU,PC
 SG_ S2A_STofCSCAutoCoding_04 : 36|4@1+ (1,0) [0|15] ""  MBMU,PC

BO_ 2332491589 S2A_SUMDATA6__05: 8 SBMU
 SG_ CRC_S2A_S6_05 : 0|8@1+ (1,0) [0|255] ""  MBMU,PC
 SG_ SBMU_Evn_T1_05 : 8|8@1+ (1,-50) [-50|205] "℃"  MBMU,PC
 SG_ SBMU_Evn_T2_05 : 16|8@1+ (1,-50) [-50|205] "℃"  MBMU,PC
 SG_ SBMU_Evn_T3_05 : 24|8@1+ (1,-50) [-50|205] "℃"  MBMU,PC
 SG_ S2A_STofCSCAutoCoding_05 : 36|4@1+ (1,0) [0|15] ""  MBMU,PC

BO_ 2332491590 S2A_SUMDATA6__06: 8 SBMU
 SG_ CRC_S2A_S6_06 : 0|8@1+ (1,0) [0|255] ""  MBMU,PC
 SG_ SBMU_Evn_T1_06 : 8|8@1+ (1,-50) [-50|205] "℃"  MBMU,PC
 SG_ SBMU_Evn_T2_06 : 16|8@1+ (1,-50) [-50|205] "℃"  MBMU,PC
 SG_ SBMU_Evn_T3_06 : 24|8@1+ (1,-50) [-50|205] "℃"  MBMU,PC
 SG_ S2A_STofCSCAutoCoding_06 : 36|4@1+ (1,0) [0|15] ""  MBMU,PC

BO_ 2332491591 S2A_SUMDATA6__07: 8 SBMU
 SG_ CRC_S2A_S6_07 : 0|8@1+ (1,0) [0|255] ""  MBMU,PC
 SG_ SBMU_Evn_T1_07 : 8|8@1+ (1,-50) [-50|205] "℃"  MBMU,PC
 SG_ SBMU_Evn_T2_07 : 16|8@1+ (1,-50) [-50|205] "℃"  MBMU,PC
 SG_ SBMU_Evn_T3_07 : 24|8@1+ (1,-50) [-50|205] "℃"  MBMU,PC
 SG_ S2A_STofCSCAutoCoding_07 : 36|4@1+ (1,0) [0|15] ""  MBMU,PC

BO_ 2332491592 S2A_SUMDATA6__08: 8 SBMU
 SG_ CRC_S2A_S6_08 : 0|8@1+ (1,0) [0|255] ""  MBMU,PC
 SG_ SBMU_Evn_T1_08 : 8|8@1+ (1,-50) [-50|205] "℃"  MBMU,PC
 SG_ SBMU_Evn_T2_08 : 16|8@1+ (1,-50) [-50|205] "℃"  MBMU,PC
 SG_ SBMU_Evn_T3_08 : 24|8@1+ (1,-50) [-50|205] "℃"  MBMU,PC
 SG_ S2A_STofCSCAutoCoding_08 : 36|4@1+ (1,0) [0|15] ""  MBMU,PC

BO_ 2332491593 S2A_SUMDATA6__09: 8 SBMU
 SG_ CRC_S2A_S6_09 : 0|8@1+ (1,0) [0|255] ""  MBMU,PC
 SG_ SBMU_Evn_T1_09 : 8|8@1+ (1,-50) [-50|205] "℃"  MBMU,PC
 SG_ SBMU_Evn_T2_09 : 16|8@1+ (1,-50) [-50|205] "℃"  MBMU,PC
 SG_ SBMU_Evn_T3_09 : 24|8@1+ (1,-50) [-50|205] "℃"  MBMU,PC
 SG_ S2A_STofCSCAutoCoding_09 : 36|4@1+ (1,0) [0|15] ""  MBMU,PC

BO_ 2332491594 S2A_SUMDATA6__10: 8 SBMU
 SG_ CRC_S2A_S6_10 : 0|8@1+ (1,0) [0|255] ""  MBMU,PC
 SG_ SBMU_Evn_T1_10 : 8|8@1+ (1,-50) [-50|205] "℃"  MBMU,PC
 SG_ SBMU_Evn_T2_10 : 16|8@1+ (1,-50) [-50|205] "℃"  MBMU,PC
 SG_ SBMU_Evn_T3_10 : 24|8@1+ (1,-50) [-50|205] "℃"  MBMU,PC
 SG_ S2A_STofCSCAutoCoding_10 : 36|4@1+ (1,0) [0|15] ""  MBMU,PC

BO_ 2332491595 S2A_SUMDATA6__11: 8 SBMU
 SG_ CRC_S2A_S6_11 : 0|8@1+ (1,0) [0|255] ""  MBMU,PC
 SG_ SBMU_Evn_T1_11 : 8|8@1+ (1,-50) [-50|205] "℃"  MBMU,PC
 SG_ SBMU_Evn_T2_11 : 16|8@1+ (1,-50) [-50|205] "℃"  MBMU,PC
 SG_ SBMU_Evn_T3_11 : 24|8@1+ (1,-50) [-50|205] "℃"  MBMU,PC
 SG_ S2A_STofCSCAutoCoding_11 : 36|4@1+ (1,0) [0|15] ""  MBMU,PC

BO_ 2332491596 S2A_SUMDATA6__12: 8 SBMU
 SG_ CRC_S2A_S6_12 : 0|8@1+ (1,0) [0|255] ""  MBMU,PC
 SG_ SBMU_Evn_T1_12 : 8|8@1+ (1,-50) [-50|205] "℃"  MBMU,PC
 SG_ SBMU_Evn_T2_12 : 16|8@1+ (1,-50) [-50|205] "℃"  MBMU,PC
 SG_ SBMU_Evn_T3_12 : 24|8@1+ (1,-50) [-50|205] "℃"  MBMU,PC
 SG_ S2A_STofCSCAutoCoding_12 : 36|4@1+ (1,0) [0|15] ""  MBMU,PC

BO_ 2332491597 S2A_SUMDATA6__13: 8 SBMU
 SG_ CRC_S2A_S6_13 : 0|8@1+ (1,0) [0|255] ""  MBMU,PC
 SG_ SBMU_Evn_T1_13 : 8|8@1+ (1,-50) [-50|205] "℃"  MBMU,PC
 SG_ SBMU_Evn_T2_13 : 16|8@1+ (1,-50) [-50|205] "℃"  MBMU,PC
 SG_ SBMU_Evn_T3_13 : 24|8@1+ (1,-50) [-50|205] "℃"  MBMU,PC
 SG_ S2A_STofCSCAutoCoding_13 : 36|4@1+ (1,0) [0|15] ""  MBMU,PC

BO_ 2332491598 S2A_SUMDATA6__14: 8 SBMU
 SG_ CRC_S2A_S6_14 : 0|8@1+ (1,0) [0|255] ""  MBMU,PC
 SG_ SBMU_Evn_T1_14 : 8|8@1+ (1,-50) [-50|205] "℃"  MBMU,PC
 SG_ SBMU_Evn_T2_14 : 16|8@1+ (1,-50) [-50|205] "℃"  MBMU,PC
 SG_ SBMU_Evn_T3_14 : 24|8@1+ (1,-50) [-50|205] "℃"  MBMU,PC
 SG_ S2A_STofCSCAutoCoding_14 : 36|4@1+ (1,0) [0|15] ""  MBMU,PC

BO_ 2332491599 S2A_SUMDATA6__15: 8 SBMU
 SG_ CRC_S2A_S6_15 : 0|8@1+ (1,0) [0|255] ""  MBMU,PC
 SG_ SBMU_Evn_T1_15 : 8|8@1+ (1,-50) [-50|205] "℃"  MBMU,PC
 SG_ SBMU_Evn_T2_15 : 16|8@1+ (1,-50) [-50|205] "℃"  MBMU,PC
 SG_ SBMU_Evn_T3_15 : 24|8@1+ (1,-50) [-50|205] "℃"  MBMU,PC
 SG_ S2A_STofCSCAutoCoding_15 : 36|4@1+ (1,0) [0|15] ""  MBMU,PC

BO_ 2332491600 S2A_SUMDATA6__16: 8 SBMU
 SG_ CRC_S2A_S6_16 : 0|8@1+ (1,0) [0|255] ""  MBMU,PC
 SG_ SBMU_Evn_T1_16 : 8|8@1+ (1,-50) [-50|205] "℃"  MBMU,PC
 SG_ SBMU_Evn_T2_16 : 16|8@1+ (1,-50) [-50|205] "℃"  MBMU,PC
 SG_ SBMU_Evn_T3_16 : 24|8@1+ (1,-50) [-50|205] "℃"  MBMU,PC
 SG_ S2A_STofCSCAutoCoding_16 : 36|4@1+ (1,0) [0|15] ""  MBMU,PC

BO_ 2332491601 S2A_SUMDATA6__17: 8 SBMU
 SG_ CRC_S2A_S6_17 : 0|8@1+ (1,0) [0|255] ""  MBMU,PC
 SG_ SBMU_Evn_T1_17 : 8|8@1+ (1,-50) [-50|205] "℃"  MBMU,PC
 SG_ SBMU_Evn_T2_17 : 16|8@1+ (1,-50) [-50|205] "℃"  MBMU,PC
 SG_ SBMU_Evn_T3_17 : 24|8@1+ (1,-50) [-50|205] "℃"  MBMU,PC
 SG_ S2A_STofCSCAutoCoding_17 : 36|4@1+ (1,0) [0|15] ""  MBMU,PC

BO_ 2332491602 S2A_SUMDATA6__18: 8 SBMU
 SG_ CRC_S2A_S6_18 : 0|8@1+ (1,0) [0|255] ""  MBMU,PC
 SG_ SBMU_Evn_T1_18 : 8|8@1+ (1,-50) [-50|205] "℃"  MBMU,PC
 SG_ SBMU_Evn_T2_18 : 16|8@1+ (1,-50) [-50|205] "℃"  MBMU,PC
 SG_ SBMU_Evn_T3_18 : 24|8@1+ (1,-50) [-50|205] "℃"  MBMU,PC
 SG_ S2A_STofCSCAutoCoding_18 : 36|4@1+ (1,0) [0|15] ""  MBMU,PC

BO_ 2332491603 S2A_SUMDATA6__19: 8 SBMU
 SG_ CRC_S2A_S6_19 : 0|8@1+ (1,0) [0|255] ""  MBMU,PC
 SG_ SBMU_Evn_T1_19 : 8|8@1+ (1,-50) [-50|205] "℃"  MBMU,PC
 SG_ SBMU_Evn_T2_19 : 16|8@1+ (1,-50) [-50|205] "℃"  MBMU,PC
 SG_ SBMU_Evn_T3_19 : 24|8@1+ (1,-50) [-50|205] "℃"  MBMU,PC
 SG_ S2A_STofCSCAutoCoding_19 : 36|4@1+ (1,0) [0|15] ""  MBMU,PC

BO_ 2332491604 S2A_SUMDATA6__20: 8 SBMU
 SG_ CRC_S2A_S6_20 : 0|8@1+ (1,0) [0|255] ""  MBMU,PC
 SG_ SBMU_Evn_T1_20 : 8|8@1+ (1,-50) [-50|205] "℃"  MBMU,PC
 SG_ SBMU_Evn_T2_20 : 16|8@1+ (1,-50) [-50|205] "℃"  MBMU,PC
 SG_ SBMU_Evn_T3_20 : 24|8@1+ (1,-50) [-50|205] "℃"  MBMU,PC
 SG_ S2A_STofCSCAutoCoding_20 : 36|4@1+ (1,0) [0|15] ""  MBMU,PC

BO_ 2332491605 S2A_SUMDATA6__21: 8 SBMU
 SG_ CRC_S2A_S6_21 : 0|8@1+ (1,0) [0|255] ""  MBMU,PC
 SG_ SBMU_Evn_T1_21 : 8|8@1+ (1,-50) [-50|205] "℃"  MBMU,PC
 SG_ SBMU_Evn_T2_21 : 16|8@1+ (1,-50) [-50|205] "℃"  MBMU,PC
 SG_ SBMU_Evn_T3_21 : 24|8@1+ (1,-50) [-50|205] "℃"  MBMU,PC
 SG_ S2A_STofCSCAutoCoding_21 : 36|4@1+ (1,0) [0|15] ""  MBMU,PC

BO_ 2332491606 S2A_SUMDATA6__22: 8 SBMU
 SG_ CRC_S2A_S6_22 : 0|8@1+ (1,0) [0|255] ""  MBMU,PC
 SG_ SBMU_Evn_T1_22 : 8|8@1+ (1,-50) [-50|205] "℃"  MBMU,PC
 SG_ SBMU_Evn_T2_22 : 16|8@1+ (1,-50) [-50|205] "℃"  MBMU,PC
 SG_ SBMU_Evn_T3_22 : 24|8@1+ (1,-50) [-50|205] "℃"  MBMU,PC
 SG_ S2A_STofCSCAutoCoding_22 : 36|4@1+ (1,0) [0|15] ""  MBMU,PC

BO_ 2332491607 S2A_SUMDATA6__23: 8 SBMU
 SG_ CRC_S2A_S6_23 : 0|8@1+ (1,0) [0|255] ""  MBMU,PC
 SG_ SBMU_Evn_T1_23 : 8|8@1+ (1,-50) [-50|205] "℃"  MBMU,PC
 SG_ SBMU_Evn_T2_23 : 16|8@1+ (1,-50) [-50|205] "℃"  MBMU,PC
 SG_ SBMU_Evn_T3_23 : 24|8@1+ (1,-50) [-50|205] "℃"  MBMU,PC
 SG_ S2A_STofCSCAutoCoding_23 : 36|4@1+ (1,0) [0|15] ""  MBMU,PC

BO_ 2332491608 S2A_SUMDATA6__24: 8 SBMU
 SG_ CRC_S2A_S6_24 : 0|8@1+ (1,0) [0|255] ""  MBMU,PC
 SG_ SBMU_Evn_T1_24 : 8|8@1+ (1,-50) [-50|205] "℃"  MBMU,PC
 SG_ SBMU_Evn_T2_24 : 16|8@1+ (1,-50) [-50|205] "℃"  MBMU,PC
 SG_ SBMU_Evn_T3_24 : 24|8@1+ (1,-50) [-50|205] "℃"  MBMU,PC
 SG_ S2A_STofCSCAutoCoding_24 : 36|4@1+ (1,0) [0|15] ""  MBMU,PC

BO_ 2332491609 S2A_SUMDATA6__25: 8 SBMU
 SG_ CRC_S2A_S6_25 : 0|8@1+ (1,0) [0|255] ""  MBMU,PC
 SG_ SBMU_Evn_T1_25 : 8|8@1+ (1,-50) [-50|205] "℃"  MBMU,PC
 SG_ SBMU_Evn_T2_25 : 16|8@1+ (1,-50) [-50|205] "℃"  MBMU,PC
 SG_ SBMU_Evn_T3_25 : 24|8@1+ (1,-50) [-50|205] "℃"  MBMU,PC
 SG_ S2A_STofCSCAutoCoding_25 : 36|4@1+ (1,0) [0|15] ""  MBMU,PC

BO_ 2332491610 S2A_SUMDATA6__26: 8 SBMU
 SG_ CRC_S2A_S6_26 : 0|8@1+ (1,0) [0|255] ""  MBMU,PC
 SG_ SBMU_Evn_T1_26 : 8|8@1+ (1,-50) [-50|205] "℃"  MBMU,PC
 SG_ SBMU_Evn_T2_26 : 16|8@1+ (1,-50) [-50|205] "℃"  MBMU,PC
 SG_ SBMU_Evn_T3_26 : 24|8@1+ (1,-50) [-50|205] "℃"  MBMU,PC
 SG_ S2A_STofCSCAutoCoding_26 : 36|4@1+ (1,0) [0|15] ""  MBMU,PC

BO_ 2332491611 S2A_SUMDATA6__27: 8 SBMU
 SG_ CRC_S2A_S6_27 : 0|8@1+ (1,0) [0|255] ""  MBMU,PC
 SG_ SBMU_Evn_T1_27 : 8|8@1+ (1,-50) [-50|205] "℃"  MBMU,PC
 SG_ SBMU_Evn_T2_27 : 16|8@1+ (1,-50) [-50|205] "℃"  MBMU,PC
 SG_ SBMU_Evn_T3_27 : 24|8@1+ (1,-50) [-50|205] "℃"  MBMU,PC
 SG_ S2A_STofCSCAutoCoding_27 : 36|4@1+ (1,0) [0|15] ""  MBMU,PC

BO_ 2332491612 S2A_SUMDATA6__28: 8 SBMU
 SG_ CRC_S2A_S6_28 : 0|8@1+ (1,0) [0|255] ""  MBMU,PC
 SG_ SBMU_Evn_T1_28 : 8|8@1+ (1,-50) [-50|205] "℃"  MBMU,PC
 SG_ SBMU_Evn_T2_28 : 16|8@1+ (1,-50) [-50|205] "℃"  MBMU,PC
 SG_ SBMU_Evn_T3_28 : 24|8@1+ (1,-50) [-50|205] "℃"  MBMU,PC
 SG_ S2A_STofCSCAutoCoding_28 : 36|4@1+ (1,0) [0|15] ""  MBMU,PC

BO_ 2332491613 S2A_SUMDATA6__29: 8 SBMU
 SG_ CRC_S2A_S6_29 : 0|8@1+ (1,0) [0|255] ""  MBMU,PC
 SG_ SBMU_Evn_T1_29 : 8|8@1+ (1,-50) [-50|205] "℃"  MBMU,PC
 SG_ SBMU_Evn_T2_29 : 16|8@1+ (1,-50) [-50|205] "℃"  MBMU,PC
 SG_ SBMU_Evn_T3_29 : 24|8@1+ (1,-50) [-50|205] "℃"  MBMU,PC
 SG_ S2A_STofCSCAutoCoding_29 : 36|4@1+ (1,0) [0|15] ""  MBMU,PC

BO_ 2332491614 S2A_SUMDATA6__30: 8 SBMU
 SG_ CRC_S2A_S6_30 : 0|8@1+ (1,0) [0|255] ""  MBMU,PC
 SG_ SBMU_Evn_T1_30 : 8|8@1+ (1,-50) [-50|205] "℃"  MBMU,PC
 SG_ SBMU_Evn_T2_30 : 16|8@1+ (1,-50) [-50|205] "℃"  MBMU,PC
 SG_ SBMU_Evn_T3_30 : 24|8@1+ (1,-50) [-50|205] "℃"  MBMU,PC
 SG_ S2A_STofCSCAutoCoding_30 : 36|4@1+ (1,0) [0|15] ""  MBMU,PC

BO_ 2332491615 S2A_SUMDATA6__31: 8 SBMU
 SG_ CRC_S2A_S6_31 : 0|8@1+ (1,0) [0|255] ""  MBMU,PC
 SG_ SBMU_Evn_T1_31 : 8|8@1+ (1,-50) [-50|205] "℃"  MBMU,PC
 SG_ SBMU_Evn_T2_31 : 16|8@1+ (1,-50) [-50|205] "℃"  MBMU,PC
 SG_ SBMU_Evn_T3_31 : 24|8@1+ (1,-50) [-50|205] "℃"  MBMU,PC
 SG_ S2A_STofCSCAutoCoding_31 : 36|4@1+ (1,0) [0|15] ""  MBMU,PC

BO_ 2332491616 S2A_SUMDATA6__32: 8 SBMU
 SG_ CRC_S2A_S6_32 : 0|8@1+ (1,0) [0|255] ""  MBMU,PC
 SG_ SBMU_Evn_T1_32 : 8|8@1+ (1,-50) [-50|205] "℃"  MBMU,PC
 SG_ SBMU_Evn_T2_32 : 16|8@1+ (1,-50) [-50|205] "℃"  MBMU,PC
 SG_ SBMU_Evn_T3_32 : 24|8@1+ (1,-50) [-50|205] "℃"  MBMU,PC
 SG_ S2A_STofCSCAutoCoding_32 : 36|4@1+ (1,0) [0|15] ""  MBMU,PC

BO_ 2332491617 S2A_SUMDATA6__33: 8 SBMU
 SG_ CRC_S2A_S6_33 : 0|8@1+ (1,0) [0|255] ""  MBMU,PC
 SG_ SBMU_Evn_T1_33 : 8|8@1+ (1,-50) [-50|205] "℃"  MBMU,PC
 SG_ SBMU_Evn_T2_33 : 16|8@1+ (1,-50) [-50|205] "℃"  MBMU,PC
 SG_ SBMU_Evn_T3_33 : 24|8@1+ (1,-50) [-50|205] "℃"  MBMU,PC
 SG_ S2A_STofCSCAutoCoding_33 : 36|4@1+ (1,0) [0|15] ""  MBMU,PC

BO_ 2332491618 S2A_SUMDATA6__34: 8 SBMU
 SG_ CRC_S2A_S6_34 : 0|8@1+ (1,0) [0|255] ""  MBMU,PC
 SG_ SBMU_Evn_T1_34 : 8|8@1+ (1,-50) [-50|205] "℃"  MBMU,PC
 SG_ SBMU_Evn_T2_34 : 16|8@1+ (1,-50) [-50|205] "℃"  MBMU,PC
 SG_ SBMU_Evn_T3_34 : 24|8@1+ (1,-50) [-50|205] "℃"  MBMU,PC
 SG_ S2A_STofCSCAutoCoding_34 : 36|4@1+ (1,0) [0|15] ""  MBMU,PC

BO_ 2332491619 S2A_SUMDATA6__35: 8 SBMU
 SG_ CRC_S2A_S6_35 : 0|8@1+ (1,0) [0|255] ""  MBMU,PC
 SG_ SBMU_Evn_T1_35 : 8|8@1+ (1,-50) [-50|205] "℃"  MBMU,PC
 SG_ SBMU_Evn_T2_35 : 16|8@1+ (1,-50) [-50|205] "℃"  MBMU,PC
 SG_ SBMU_Evn_T3_35 : 24|8@1+ (1,-50) [-50|205] "℃"  MBMU,PC
 SG_ S2A_STofCSCAutoCoding_35 : 36|4@1+ (1,0) [0|15] ""  MBMU,PC

BO_ 2332491620 S2A_SUMDATA6__36: 8 SBMU
 SG_ CRC_S2A_S6_36 : 0|8@1+ (1,0) [0|255] ""  MBMU,PC
 SG_ SBMU_Evn_T1_36 : 8|8@1+ (1,-50) [-50|205] "℃"  MBMU,PC
 SG_ SBMU_Evn_T2_36 : 16|8@1+ (1,-50) [-50|205] "℃"  MBMU,PC
 SG_ SBMU_Evn_T3_36 : 24|8@1+ (1,-50) [-50|205] "℃"  MBMU,PC
 SG_ S2A_STofCSCAutoCoding_36 : 36|4@1+ (1,0) [0|15] ""  MBMU,PC

BO_ 2332491621 S2A_SUMDATA6__37: 8 SBMU
 SG_ CRC_S2A_S6_37 : 0|8@1+ (1,0) [0|255] ""  MBMU,PC
 SG_ SBMU_Evn_T1_37 : 8|8@1+ (1,-50) [-50|205] "℃"  MBMU,PC
 SG_ SBMU_Evn_T2_37 : 16|8@1+ (1,-50) [-50|205] "℃"  MBMU,PC
 SG_ SBMU_Evn_T3_37 : 24|8@1+ (1,-50) [-50|205] "℃"  MBMU,PC
 SG_ S2A_STofCSCAutoCoding_37 : 36|4@1+ (1,0) [0|15] ""  MBMU,PC

BO_ 2332491622 S2A_SUMDATA6__38: 8 SBMU
 SG_ CRC_S2A_S6_38 : 0|8@1+ (1,0) [0|255] ""  MBMU,PC
 SG_ SBMU_Evn_T1_38 : 8|8@1+ (1,-50) [-50|205] "℃"  MBMU,PC
 SG_ SBMU_Evn_T2_38 : 16|8@1+ (1,-50) [-50|205] "℃"  MBMU,PC
 SG_ SBMU_Evn_T3_38 : 24|8@1+ (1,-50) [-50|205] "℃"  MBMU,PC
 SG_ S2A_STofCSCAutoCoding_38 : 36|4@1+ (1,0) [0|15] ""  MBMU,PC

BO_ 2332491623 S2A_SUMDATA6__39: 8 SBMU
 SG_ CRC_S2A_S6_39 : 0|8@1+ (1,0) [0|255] ""  MBMU,PC
 SG_ SBMU_Evn_T1_39 : 8|8@1+ (1,-50) [-50|205] "℃"  MBMU,PC
 SG_ SBMU_Evn_T2_39 : 16|8@1+ (1,-50) [-50|205] "℃"  MBMU,PC
 SG_ SBMU_Evn_T3_39 : 24|8@1+ (1,-50) [-50|205] "℃"  MBMU,PC
 SG_ S2A_STofCSCAutoCoding_39 : 36|4@1+ (1,0) [0|15] ""  MBMU,PC

BO_ 2332491624 S2A_SUMDATA6__40: 8 SBMU
 SG_ CRC_S2A_S6_40 : 0|8@1+ (1,0) [0|255] ""  MBMU,PC
 SG_ SBMU_Evn_T1_40 : 8|8@1+ (1,-50) [-50|205] "℃"  MBMU,PC
 SG_ SBMU_Evn_T2_40 : 16|8@1+ (1,-50) [-50|205] "℃"  MBMU,PC
 SG_ SBMU_Evn_T3_40 : 24|8@1+ (1,-50) [-50|205] "℃"  MBMU,PC
 SG_ S2A_STofCSCAutoCoding_40 : 36|4@1+ (1,0) [0|15] ""  MBMU,PC

BO_ 2332491625 S2A_SUMDATA6__41: 8 SBMU
 SG_ CRC_S2A_S6_41 : 0|8@1+ (1,0) [0|255] ""  MBMU,PC
 SG_ SBMU_Evn_T1_41 : 8|8@1+ (1,-50) [-50|205] "℃"  MBMU,PC
 SG_ SBMU_Evn_T2_41 : 16|8@1+ (1,-50) [-50|205] "℃"  MBMU,PC
 SG_ SBMU_Evn_T3_41 : 24|8@1+ (1,-50) [-50|205] "℃"  MBMU,PC
 SG_ S2A_STofCSCAutoCoding_41 : 36|4@1+ (1,0) [0|15] ""  MBMU,PC

BO_ 2332491626 S2A_SUMDATA6__42: 8 SBMU
 SG_ CRC_S2A_S6_42 : 0|8@1+ (1,0) [0|255] ""  MBMU,PC
 SG_ SBMU_Evn_T1_42 : 8|8@1+ (1,-50) [-50|205] "℃"  MBMU,PC
 SG_ SBMU_Evn_T2_42 : 16|8@1+ (1,-50) [-50|205] "℃"  MBMU,PC
 SG_ SBMU_Evn_T3_42 : 24|8@1+ (1,-50) [-50|205] "℃"  MBMU,PC
 SG_ S2A_STofCSCAutoCoding_42 : 36|4@1+ (1,0) [0|15] ""  MBMU,PC

BO_ 2332491627 S2A_SUMDATA6__43: 8 SBMU
 SG_ CRC_S2A_S6_43 : 0|8@1+ (1,0) [0|255] ""  MBMU,PC
 SG_ SBMU_Evn_T1_43 : 8|8@1+ (1,-50) [-50|205] "℃"  MBMU,PC
 SG_ SBMU_Evn_T2_43 : 16|8@1+ (1,-50) [-50|205] "℃"  MBMU,PC
 SG_ SBMU_Evn_T3_43 : 24|8@1+ (1,-50) [-50|205] "℃"  MBMU,PC
 SG_ S2A_STofCSCAutoCoding_43 : 36|4@1+ (1,0) [0|15] ""  MBMU,PC

BO_ 2332491628 S2A_SUMDATA6__44: 8 SBMU
 SG_ CRC_S2A_S6_44 : 0|8@1+ (1,0) [0|255] ""  MBMU,PC
 SG_ SBMU_Evn_T1_44 : 8|8@1+ (1,-50) [-50|205] "℃"  MBMU,PC
 SG_ SBMU_Evn_T2_44 : 16|8@1+ (1,-50) [-50|205] "℃"  MBMU,PC
 SG_ SBMU_Evn_T3_44 : 24|8@1+ (1,-50) [-50|205] "℃"  MBMU,PC
 SG_ S2A_STofCSCAutoCoding_44 : 36|4@1+ (1,0) [0|15] ""  MBMU,PC

BO_ 2332491629 S2A_SUMDATA6__45: 8 SBMU
 SG_ CRC_S2A_S6_45 : 0|8@1+ (1,0) [0|255] ""  MBMU,PC
 SG_ SBMU_Evn_T1_45 : 8|8@1+ (1,-50) [-50|205] "℃"  MBMU,PC
 SG_ SBMU_Evn_T2_45 : 16|8@1+ (1,-50) [-50|205] "℃"  MBMU,PC
 SG_ SBMU_Evn_T3_45 : 24|8@1+ (1,-50) [-50|205] "℃"  MBMU,PC
 SG_ S2A_STofCSCAutoCoding_45 : 36|4@1+ (1,0) [0|15] ""  MBMU,PC

BO_ 2332491630 S2A_SUMDATA6__46: 8 SBMU
 SG_ CRC_S2A_S6_46 : 0|8@1+ (1,0) [0|255] ""  MBMU,PC
 SG_ SBMU_Evn_T1_46 : 8|8@1+ (1,-50) [-50|205] "℃"  MBMU,PC
 SG_ SBMU_Evn_T2_46 : 16|8@1+ (1,-50) [-50|205] "℃"  MBMU,PC
 SG_ SBMU_Evn_T3_46 : 24|8@1+ (1,-50) [-50|205] "℃"  MBMU,PC
 SG_ S2A_STofCSCAutoCoding_46 : 36|4@1+ (1,0) [0|15] ""  MBMU,PC

BO_ 2332491631 S2A_SUMDATA6__47: 8 SBMU
 SG_ CRC_S2A_S6_47 : 0|8@1+ (1,0) [0|255] ""  MBMU,PC
 SG_ SBMU_Evn_T1_47 : 8|8@1+ (1,-50) [-50|205] "℃"  MBMU,PC
 SG_ SBMU_Evn_T2_47 : 16|8@1+ (1,-50) [-50|205] "℃"  MBMU,PC
 SG_ SBMU_Evn_T3_47 : 24|8@1+ (1,-50) [-50|205] "℃"  MBMU,PC
 SG_ S2A_STofCSCAutoCoding_47 : 36|4@1+ (1,0) [0|15] ""  MBMU,PC

BO_ 2332491632 S2A_SUMDATA6__48: 8 SBMU
 SG_ CRC_S2A_S6_48 : 0|8@1+ (1,0) [0|255] ""  MBMU,PC
 SG_ SBMU_Evn_T1_48 : 8|8@1+ (1,-50) [-50|205] "℃"  MBMU,PC
 SG_ SBMU_Evn_T2_48 : 16|8@1+ (1,-50) [-50|205] "℃"  MBMU,PC
 SG_ SBMU_Evn_T3_48 : 24|8@1+ (1,-50) [-50|205] "℃"  MBMU,PC
 SG_ S2A_STofCSCAutoCoding_48 : 36|4@1+ (1,0) [0|15] ""  MBMU,PC

BO_ 2332491633 S2A_SUMDATA6__49: 8 SBMU
 SG_ CRC_S2A_S6_49 : 0|8@1+ (1,0) [0|255] ""  MBMU,PC
 SG_ SBMU_Evn_T1_49 : 8|8@1+ (1,-50) [-50|205] "℃"  MBMU,PC
 SG_ SBMU_Evn_T2_49 : 16|8@1+ (1,-50) [-50|205] "℃"  MBMU,PC
 SG_ SBMU_Evn_T3_49 : 24|8@1+ (1,-50) [-50|205] "℃"  MBMU,PC
 SG_ S2A_STofCSCAutoCoding_49 : 36|4@1+ (1,0) [0|15] ""  MBMU,PC

BO_ 2332491634 S2A_SUMDATA6__50: 8 SBMU
 SG_ CRC_S2A_S6_50 : 0|8@1+ (1,0) [0|255] ""  MBMU,PC
 SG_ SBMU_Evn_T1_50 : 8|8@1+ (1,-50) [-50|205] "℃"  MBMU,PC
 SG_ SBMU_Evn_T2_50 : 16|8@1+ (1,-50) [-50|205] "℃"  MBMU,PC
 SG_ SBMU_Evn_T3_50 : 24|8@1+ (1,-50) [-50|205] "℃"  MBMU,PC
 SG_ S2A_STofCSCAutoCoding_50 : 36|4@1+ (1,0) [0|15] ""  MBMU,PC

BO_ 2332491635 S2A_SUMDATA6__51: 8 SBMU
 SG_ CRC_S2A_S6_51 : 0|8@1+ (1,0) [0|255] ""  MBMU,PC
 SG_ SBMU_Evn_T1_51 : 8|8@1+ (1,-50) [-50|205] "℃"  MBMU,PC
 SG_ SBMU_Evn_T2_51 : 16|8@1+ (1,-50) [-50|205] "℃"  MBMU,PC
 SG_ SBMU_Evn_T3_51 : 24|8@1+ (1,-50) [-50|205] "℃"  MBMU,PC
 SG_ S2A_STofCSCAutoCoding_51 : 36|4@1+ (1,0) [0|15] ""  MBMU,PC

BO_ 2332491636 S2A_SUMDATA6__52: 8 SBMU
 SG_ CRC_S2A_S6_52 : 0|8@1+ (1,0) [0|255] ""  MBMU,PC
 SG_ SBMU_Evn_T1_52 : 8|8@1+ (1,-50) [-50|205] "℃"  MBMU,PC
 SG_ SBMU_Evn_T2_52 : 16|8@1+ (1,-50) [-50|205] "℃"  MBMU,PC
 SG_ SBMU_Evn_T3_52 : 24|8@1+ (1,-50) [-50|205] "℃"  MBMU,PC
 SG_ S2A_STofCSCAutoCoding_52 : 36|4@1+ (1,0) [0|15] ""  MBMU,PC

BO_ 2332491637 S2A_SUMDATA6__53: 8 SBMU
 SG_ CRC_S2A_S6_53 : 0|8@1+ (1,0) [0|255] ""  MBMU,PC
 SG_ SBMU_Evn_T1_53 : 8|8@1+ (1,-50) [-50|205] "℃"  MBMU,PC
 SG_ SBMU_Evn_T2_53 : 16|8@1+ (1,-50) [-50|205] "℃"  MBMU,PC
 SG_ SBMU_Evn_T3_53 : 24|8@1+ (1,-50) [-50|205] "℃"  MBMU,PC
 SG_ S2A_STofCSCAutoCoding_53 : 36|4@1+ (1,0) [0|15] ""  MBMU,PC

BO_ 2332491638 S2A_SUMDATA6__54: 8 SBMU
 SG_ CRC_S2A_S6_54 : 0|8@1+ (1,0) [0|255] ""  MBMU,PC
 SG_ SBMU_Evn_T1_54 : 8|8@1+ (1,-50) [-50|205] "℃"  MBMU,PC
 SG_ SBMU_Evn_T2_54 : 16|8@1+ (1,-50) [-50|205] "℃"  MBMU,PC
 SG_ SBMU_Evn_T3_54 : 24|8@1+ (1,-50) [-50|205] "℃"  MBMU,PC
 SG_ S2A_STofCSCAutoCoding_54 : 36|4@1+ (1,0) [0|15] ""  MBMU,PC

BO_ 2332491639 S2A_SUMDATA6__55: 8 SBMU
 SG_ CRC_S2A_S6_55 : 0|8@1+ (1,0) [0|255] ""  MBMU,PC
 SG_ SBMU_Evn_T1_55 : 8|8@1+ (1,-50) [-50|205] "℃"  MBMU,PC
 SG_ SBMU_Evn_T2_55 : 16|8@1+ (1,-50) [-50|205] "℃"  MBMU,PC
 SG_ SBMU_Evn_T3_55 : 24|8@1+ (1,-50) [-50|205] "℃"  MBMU,PC
 SG_ S2A_STofCSCAutoCoding_55 : 36|4@1+ (1,0) [0|15] ""  MBMU,PC

BO_ 2332491640 S2A_SUMDATA6__56: 8 SBMU
 SG_ CRC_S2A_S6_56 : 0|8@1+ (1,0) [0|255] ""  MBMU,PC
 SG_ SBMU_Evn_T1_56 : 8|8@1+ (1,-50) [-50|205] "℃"  MBMU,PC
 SG_ SBMU_Evn_T2_56 : 16|8@1+ (1,-50) [-50|205] "℃"  MBMU,PC
 SG_ SBMU_Evn_T3_56 : 24|8@1+ (1,-50) [-50|205] "℃"  MBMU,PC
 SG_ S2A_STofCSCAutoCoding_56 : 36|4@1+ (1,0) [0|15] ""  MBMU,PC

BO_ 2332491641 S2A_SUMDATA6__57: 8 SBMU
 SG_ CRC_S2A_S6_57 : 0|8@1+ (1,0) [0|255] ""  MBMU,PC
 SG_ SBMU_Evn_T1_57 : 8|8@1+ (1,-50) [-50|205] "℃"  MBMU,PC
 SG_ SBMU_Evn_T2_57 : 16|8@1+ (1,-50) [-50|205] "℃"  MBMU,PC
 SG_ SBMU_Evn_T3_57 : 24|8@1+ (1,-50) [-50|205] "℃"  MBMU,PC
 SG_ S2A_STofCSCAutoCoding_57 : 36|4@1+ (1,0) [0|15] ""  MBMU,PC

BO_ 2332491642 S2A_SUMDATA6__58: 8 SBMU
 SG_ CRC_S2A_S6_58 : 0|8@1+ (1,0) [0|255] ""  MBMU,PC
 SG_ SBMU_Evn_T1_58 : 8|8@1+ (1,-50) [-50|205] "℃"  MBMU,PC
 SG_ SBMU_Evn_T2_58 : 16|8@1+ (1,-50) [-50|205] "℃"  MBMU,PC
 SG_ SBMU_Evn_T3_58 : 24|8@1+ (1,-50) [-50|205] "℃"  MBMU,PC
 SG_ S2A_STofCSCAutoCoding_58 : 36|4@1+ (1,0) [0|15] ""  MBMU,PC

BO_ 2332491643 S2A_SUMDATA6__59: 8 SBMU
 SG_ CRC_S2A_S6_59 : 0|8@1+ (1,0) [0|255] ""  MBMU,PC
 SG_ SBMU_Evn_T1_59 : 8|8@1+ (1,-50) [-50|205] "℃"  MBMU,PC
 SG_ SBMU_Evn_T2_59 : 16|8@1+ (1,-50) [-50|205] "℃"  MBMU,PC
 SG_ SBMU_Evn_T3_59 : 24|8@1+ (1,-50) [-50|205] "℃"  MBMU,PC
 SG_ S2A_STofCSCAutoCoding_59 : 36|4@1+ (1,0) [0|15] ""  MBMU,PC

BO_ 2332491644 S2A_SUMDATA6__60: 8 SBMU
 SG_ CRC_S2A_S6_60 : 0|8@1+ (1,0) [0|255] ""  MBMU,PC
 SG_ SBMU_Evn_T1_60 : 8|8@1+ (1,-50) [-50|205] "℃"  MBMU,PC
 SG_ SBMU_Evn_T2_60 : 16|8@1+ (1,-50) [-50|205] "℃"  MBMU,PC
 SG_ SBMU_Evn_T3_60 : 24|8@1+ (1,-50) [-50|205] "℃"  MBMU,PC
 SG_ S2A_STofCSCAutoCoding_60 : 36|4@1+ (1,0) [0|15] ""  MBMU,PC

BO_ 2332491645 S2A_SUMDATA6__61: 8 SBMU
 SG_ CRC_S2A_S6_61 : 0|8@1+ (1,0) [0|255] ""  MBMU,PC
 SG_ SBMU_Evn_T1_61 : 8|8@1+ (1,-50) [-50|205] "℃"  MBMU,PC
 SG_ SBMU_Evn_T2_61 : 16|8@1+ (1,-50) [-50|205] "℃"  MBMU,PC
 SG_ SBMU_Evn_T3_61 : 24|8@1+ (1,-50) [-50|205] "℃"  MBMU,PC
 SG_ S2A_STofCSCAutoCoding_61 : 36|4@1+ (1,0) [0|15] ""  MBMU,PC

BO_ 2332491646 S2A_SUMDATA6__62: 8 SBMU
 SG_ CRC_S2A_S6_62 : 0|8@1+ (1,0) [0|255] ""  MBMU,PC
 SG_ SBMU_Evn_T1_62 : 8|8@1+ (1,-50) [-50|205] "℃"  MBMU,PC
 SG_ SBMU_Evn_T2_62 : 16|8@1+ (1,-50) [-50|205] "℃"  MBMU,PC
 SG_ SBMU_Evn_T3_62 : 24|8@1+ (1,-50) [-50|205] "℃"  MBMU,PC
 SG_ S2A_STofCSCAutoCoding_62 : 36|4@1+ (1,0) [0|15] ""  MBMU,PC

BO_ 2332491647 S2A_SUMDATA6__63: 8 SBMU
 SG_ CRC_S2A_S6_63 : 0|8@1+ (1,0) [0|255] ""  MBMU,PC
 SG_ SBMU_Evn_T1_63 : 8|8@1+ (1,-50) [-50|205] "℃"  MBMU,PC
 SG_ SBMU_Evn_T2_63 : 16|8@1+ (1,-50) [-50|205] "℃"  MBMU,PC
 SG_ SBMU_Evn_T3_63 : 24|8@1+ (1,-50) [-50|205] "℃"  MBMU,PC
 SG_ S2A_STofCSCAutoCoding_63 : 36|4@1+ (1,0) [0|15] ""  MBMU,PC

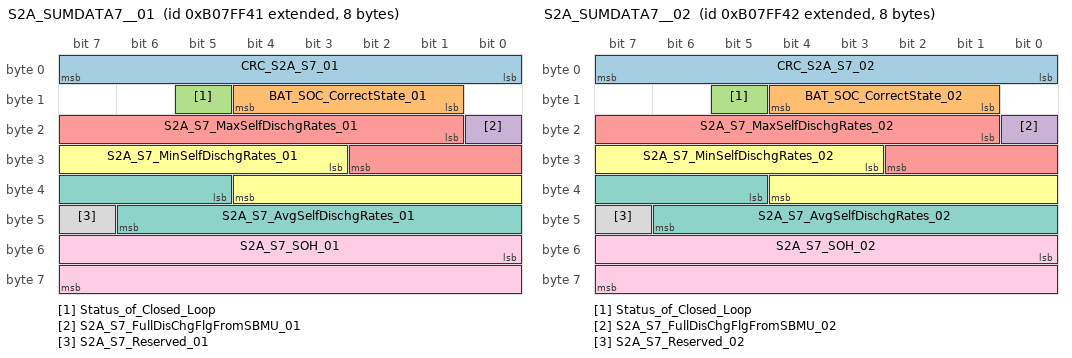
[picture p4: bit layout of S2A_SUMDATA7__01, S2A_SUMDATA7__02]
BO_ 2332557121 S2A_SUMDATA7__01: 8 SBMU
 SG_ CRC_S2A_S7_01 : 0|8@1+ (1,0) [0|255] ""  MBMU
 SG_ BAT_SOC_CorrectState_01 : 9|4@1+ (1,0) [0|15] ""  MBMU
 SG_ Status_of_Closed_Loop : 13|1@1+ (1,0) [0|1] ""  MBMU
 SG_ S2A_S7_FullDisChgFlgFromSBMU_01 : 16|1@1+ (1,0) [0|1] ""  MBMU
 SG_ S2A_S7_MaxSelfDischgRates_01 : 17|10@1+ (0.1,0) [0|102.3] "%"  MBMU,PC
 SG_ S2A_S7_MinSelfDischgRates_01 : 27|10@1+ (0.1,0) [0|102.3] "%"  MBMU,PC
 SG_ S2A_S7_AvgSelfDischgRates_01 : 37|10@1+ (0.1,0) [0|102.3] "%"  MBMU,PC
 SG_ S2A_S7_Reserved_01 : 47|1@1+ (1,0) [0|1] ""  MBMU
 SG_ S2A_S7_SOH_01 : 48|16@1+ (0.1,0) [0|6553.5] ""  MBMU

BO_ 2332557122 S2A_SUMDATA7__02: 8 SBMU
 SG_ CRC_S2A_S7_02 : 0|8@1+ (1,0) [0|255] ""  MBMU
 SG_ BAT_SOC_CorrectState_02 : 9|4@1+ (1,0) [0|15] ""  MBMU
 SG_ Status_of_Closed_Loop : 13|1@1+ (1,0) [0|1] ""  MBMU
 SG_ S2A_S7_FullDisChgFlgFromSBMU_02 : 16|1@1+ (1,0) [0|1] ""  MBMU
 SG_ S2A_S7_MaxSelfDischgRates_02 : 17|10@1+ (0.1,0) [0|102.3] "%"  MBMU,PC
 SG_ S2A_S7_MinSelfDischgRates_02 : 27|10@1+ (0.1,0) [0|102.3] "%"  MBMU,PC
 SG_ S2A_S7_AvgSelfDischgRates_02 : 37|10@1+ (0.1,0) [0|102.3] "%"  MBMU,PC
 SG_ S2A_S7_Reserved_02 : 47|1@1+ (1,0) [0|1] ""  MBMU
 SG_ S2A_S7_SOH_02 : 48|16@1+ (0.1,0) [0|6553.5] ""  MBMU

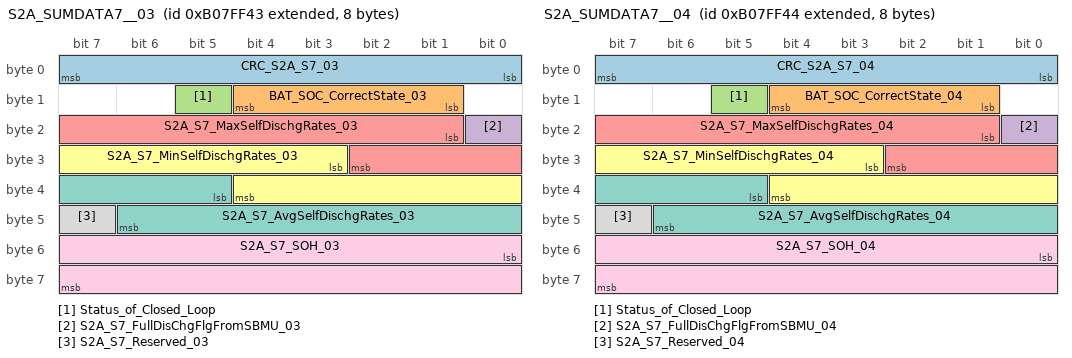
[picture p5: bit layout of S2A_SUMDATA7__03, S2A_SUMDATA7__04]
BO_ 2332557123 S2A_SUMDATA7__03: 8 SBMU
 SG_ CRC_S2A_S7_03 : 0|8@1+ (1,0) [0|255] ""  MBMU
 SG_ BAT_SOC_CorrectState_03 : 9|4@1+ (1,0) [0|15] ""  MBMU
 SG_ Status_of_Closed_Loop : 13|1@1+ (1,0) [0|1] ""  MBMU
 SG_ S2A_S7_FullDisChgFlgFromSBMU_03 : 16|1@1+ (1,0) [0|1] ""  MBMU
 SG_ S2A_S7_MaxSelfDischgRates_03 : 17|10@1+ (0.1,0) [0|102.3] "%"  MBMU,PC
 SG_ S2A_S7_MinSelfDischgRates_03 : 27|10@1+ (0.1,0) [0|102.3] "%"  MBMU,PC
 SG_ S2A_S7_AvgSelfDischgRates_03 : 37|10@1+ (0.1,0) [0|102.3] "%"  MBMU,PC
 SG_ S2A_S7_Reserved_03 : 47|1@1+ (1,0) [0|1] ""  MBMU
 SG_ S2A_S7_SOH_03 : 48|16@1+ (0.1,0) [0|6553.5] ""  MBMU

BO_ 2332557124 S2A_SUMDATA7__04: 8 SBMU
 SG_ CRC_S2A_S7_04 : 0|8@1+ (1,0) [0|255] ""  MBMU
 SG_ BAT_SOC_CorrectState_04 : 9|4@1+ (1,0) [0|15] ""  MBMU
 SG_ Status_of_Closed_Loop : 13|1@1+ (1,0) [0|1] ""  MBMU
 SG_ S2A_S7_FullDisChgFlgFromSBMU_04 : 16|1@1+ (1,0) [0|1] ""  MBMU
 SG_ S2A_S7_MaxSelfDischgRates_04 : 17|10@1+ (0.1,0) [0|102.3] "%"  MBMU,PC
 SG_ S2A_S7_MinSelfDischgRates_04 : 27|10@1+ (0.1,0) [0|102.3] "%"  MBMU,PC
 SG_ S2A_S7_AvgSelfDischgRates_04 : 37|10@1+ (0.1,0) [0|102.3] "%"  MBMU,PC
 SG_ S2A_S7_Reserved_04 : 47|1@1+ (1,0) [0|1] ""  MBMU
 SG_ S2A_S7_SOH_04 : 48|16@1+ (0.1,0) [0|6553.5] ""  MBMU

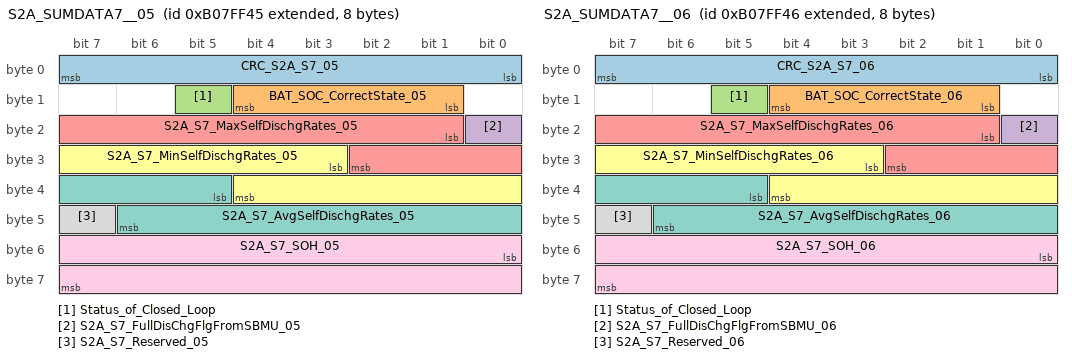
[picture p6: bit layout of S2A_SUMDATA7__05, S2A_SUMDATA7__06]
BO_ 2332557125 S2A_SUMDATA7__05: 8 SBMU
 SG_ CRC_S2A_S7_05 : 0|8@1+ (1,0) [0|255] ""  MBMU
 SG_ BAT_SOC_CorrectState_05 : 9|4@1+ (1,0) [0|15] ""  MBMU
 SG_ Status_of_Closed_Loop : 13|1@1+ (1,0) [0|1] ""  MBMU
 SG_ S2A_S7_FullDisChgFlgFromSBMU_05 : 16|1@1+ (1,0) [0|1] ""  MBMU
 SG_ S2A_S7_MaxSelfDischgRates_05 : 17|10@1+ (0.1,0) [0|102.3] "%"  MBMU,PC
 SG_ S2A_S7_MinSelfDischgRates_05 : 27|10@1+ (0.1,0) [0|102.3] "%"  MBMU,PC
 SG_ S2A_S7_AvgSelfDischgRates_05 : 37|10@1+ (0.1,0) [0|102.3] "%"  MBMU,PC
 SG_ S2A_S7_Reserved_05 : 47|1@1+ (1,0) [0|1] ""  MBMU
 SG_ S2A_S7_SOH_05 : 48|16@1+ (0.1,0) [0|6553.5] ""  MBMU

BO_ 2332557126 S2A_SUMDATA7__06: 8 SBMU
 SG_ CRC_S2A_S7_06 : 0|8@1+ (1,0) [0|255] ""  MBMU
 SG_ BAT_SOC_CorrectState_06 : 9|4@1+ (1,0) [0|15] ""  MBMU
 SG_ Status_of_Closed_Loop : 13|1@1+ (1,0) [0|1] ""  MBMU
 SG_ S2A_S7_FullDisChgFlgFromSBMU_06 : 16|1@1+ (1,0) [0|1] ""  MBMU
 SG_ S2A_S7_MaxSelfDischgRates_06 : 17|10@1+ (0.1,0) [0|102.3] "%"  MBMU,PC
 SG_ S2A_S7_MinSelfDischgRates_06 : 27|10@1+ (0.1,0) [0|102.3] "%"  MBMU,PC
 SG_ S2A_S7_AvgSelfDischgRates_06 : 37|10@1+ (0.1,0) [0|102.3] "%"  MBMU,PC
 SG_ S2A_S7_Reserved_06 : 47|1@1+ (1,0) [0|1] ""  MBMU
 SG_ S2A_S7_SOH_06 : 48|16@1+ (0.1,0) [0|6553.5] ""  MBMU

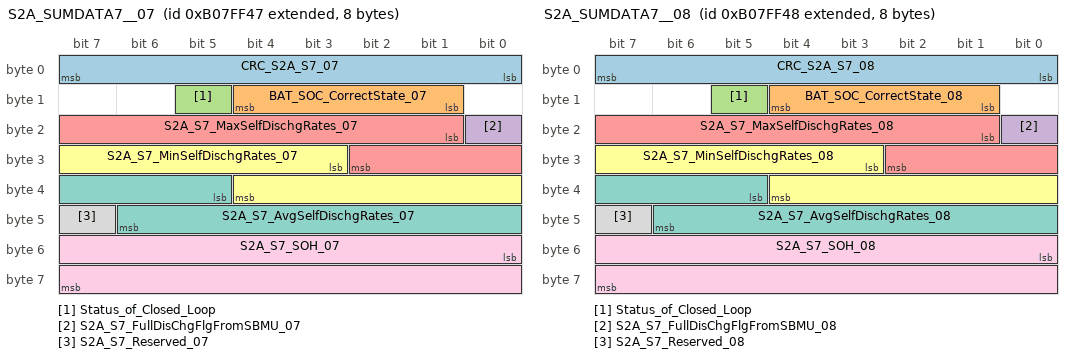
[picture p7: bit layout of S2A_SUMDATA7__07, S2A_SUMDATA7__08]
BO_ 2332557127 S2A_SUMDATA7__07: 8 SBMU
 SG_ CRC_S2A_S7_07 : 0|8@1+ (1,0) [0|255] ""  MBMU
 SG_ BAT_SOC_CorrectState_07 : 9|4@1+ (1,0) [0|15] ""  MBMU
 SG_ Status_of_Closed_Loop : 13|1@1+ (1,0) [0|1] ""  MBMU
 SG_ S2A_S7_FullDisChgFlgFromSBMU_07 : 16|1@1+ (1,0) [0|1] ""  MBMU
 SG_ S2A_S7_MaxSelfDischgRates_07 : 17|10@1+ (0.1,0) [0|102.3] "%"  MBMU,PC
 SG_ S2A_S7_MinSelfDischgRates_07 : 27|10@1+ (0.1,0) [0|102.3] "%"  MBMU,PC
 SG_ S2A_S7_AvgSelfDischgRates_07 : 37|10@1+ (0.1,0) [0|102.3] "%"  MBMU,PC
 SG_ S2A_S7_Reserved_07 : 47|1@1+ (1,0) [0|1] ""  MBMU
 SG_ S2A_S7_SOH_07 : 48|16@1+ (0.1,0) [0|6553.5] ""  MBMU

BO_ 2332557128 S2A_SUMDATA7__08: 8 SBMU
 SG_ CRC_S2A_S7_08 : 0|8@1+ (1,0) [0|255] ""  MBMU
 SG_ BAT_SOC_CorrectState_08 : 9|4@1+ (1,0) [0|15] ""  MBMU
 SG_ Status_of_Closed_Loop : 13|1@1+ (1,0) [0|1] ""  MBMU
 SG_ S2A_S7_FullDisChgFlgFromSBMU_08 : 16|1@1+ (1,0) [0|1] ""  MBMU
 SG_ S2A_S7_MaxSelfDischgRates_08 : 17|10@1+ (0.1,0) [0|102.3] "%"  MBMU,PC
 SG_ S2A_S7_MinSelfDischgRates_08 : 27|10@1+ (0.1,0) [0|102.3] "%"  MBMU,PC
 SG_ S2A_S7_AvgSelfDischgRates_08 : 37|10@1+ (0.1,0) [0|102.3] "%"  MBMU,PC
 SG_ S2A_S7_Reserved_08 : 47|1@1+ (1,0) [0|1] ""  MBMU
 SG_ S2A_S7_SOH_08 : 48|16@1+ (0.1,0) [0|6553.5] ""  MBMU

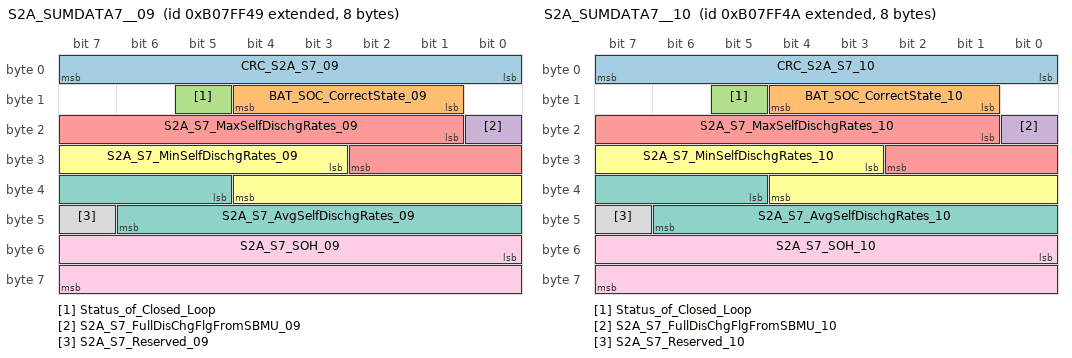
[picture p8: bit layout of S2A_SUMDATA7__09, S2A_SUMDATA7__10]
BO_ 2332557129 S2A_SUMDATA7__09: 8 SBMU
 SG_ CRC_S2A_S7_09 : 0|8@1+ (1,0) [0|255] ""  MBMU
 SG_ BAT_SOC_CorrectState_09 : 9|4@1+ (1,0) [0|15] ""  MBMU
 SG_ Status_of_Closed_Loop : 13|1@1+ (1,0) [0|1] ""  MBMU
 SG_ S2A_S7_FullDisChgFlgFromSBMU_09 : 16|1@1+ (1,0) [0|1] ""  MBMU
 SG_ S2A_S7_MaxSelfDischgRates_09 : 17|10@1+ (0.1,0) [0|102.3] "%"  MBMU,PC
 SG_ S2A_S7_MinSelfDischgRates_09 : 27|10@1+ (0.1,0) [0|102.3] "%"  MBMU,PC
 SG_ S2A_S7_AvgSelfDischgRates_09 : 37|10@1+ (0.1,0) [0|102.3] "%"  MBMU,PC
 SG_ S2A_S7_Reserved_09 : 47|1@1+ (1,0) [0|1] ""  MBMU
 SG_ S2A_S7_SOH_09 : 48|16@1+ (0.1,0) [0|6553.5] ""  MBMU

BO_ 2332557130 S2A_SUMDATA7__10: 8 SBMU
 SG_ CRC_S2A_S7_10 : 0|8@1+ (1,0) [0|255] ""  MBMU
 SG_ BAT_SOC_CorrectState_10 : 9|4@1+ (1,0) [0|15] ""  MBMU
 SG_ Status_of_Closed_Loop : 13|1@1+ (1,0) [0|1] ""  MBMU
 SG_ S2A_S7_FullDisChgFlgFromSBMU_10 : 16|1@1+ (1,0) [0|1] ""  MBMU
 SG_ S2A_S7_MaxSelfDischgRates_10 : 17|10@1+ (0.1,0) [0|102.3] "%"  MBMU,PC
 SG_ S2A_S7_MinSelfDischgRates_10 : 27|10@1+ (0.1,0) [0|102.3] "%"  MBMU,PC
 SG_ S2A_S7_AvgSelfDischgRates_10 : 37|10@1+ (0.1,0) [0|102.3] "%"  MBMU,PC
 SG_ S2A_S7_Reserved_10 : 47|1@1+ (1,0) [0|1] ""  MBMU
 SG_ S2A_S7_SOH_10 : 48|16@1+ (0.1,0) [0|6553.5] ""  MBMU

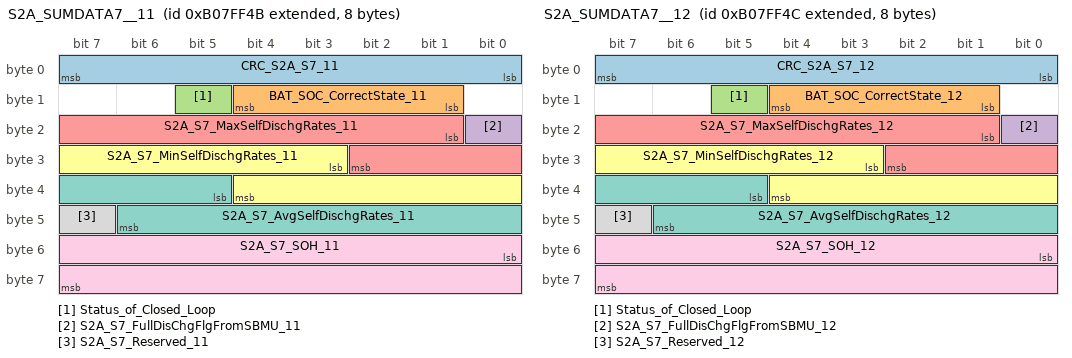
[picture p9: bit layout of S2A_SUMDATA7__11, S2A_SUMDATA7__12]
BO_ 2332557131 S2A_SUMDATA7__11: 8 SBMU
 SG_ CRC_S2A_S7_11 : 0|8@1+ (1,0) [0|255] ""  MBMU
 SG_ BAT_SOC_CorrectState_11 : 9|4@1+ (1,0) [0|15] ""  MBMU
 SG_ Status_of_Closed_Loop : 13|1@1+ (1,0) [0|1] ""  MBMU
 SG_ S2A_S7_FullDisChgFlgFromSBMU_11 : 16|1@1+ (1,0) [0|1] ""  MBMU
 SG_ S2A_S7_MaxSelfDischgRates_11 : 17|10@1+ (0.1,0) [0|102.3] "%"  MBMU,PC
 SG_ S2A_S7_MinSelfDischgRates_11 : 27|10@1+ (0.1,0) [0|102.3] "%"  MBMU,PC
 SG_ S2A_S7_AvgSelfDischgRates_11 : 37|10@1+ (0.1,0) [0|102.3] "%"  MBMU,PC
 SG_ S2A_S7_Reserved_11 : 47|1@1+ (1,0) [0|1] ""  MBMU
 SG_ S2A_S7_SOH_11 : 48|16@1+ (0.1,0) [0|6553.5] ""  MBMU

BO_ 2332557132 S2A_SUMDATA7__12: 8 SBMU
 SG_ CRC_S2A_S7_12 : 0|8@1+ (1,0) [0|255] ""  MBMU
 SG_ BAT_SOC_CorrectState_12 : 9|4@1+ (1,0) [0|15] ""  MBMU
 SG_ Status_of_Closed_Loop : 13|1@1+ (1,0) [0|1] ""  MBMU
 SG_ S2A_S7_FullDisChgFlgFromSBMU_12 : 16|1@1+ (1,0) [0|1] ""  MBMU
 SG_ S2A_S7_MaxSelfDischgRates_12 : 17|10@1+ (0.1,0) [0|102.3] "%"  MBMU,PC
 SG_ S2A_S7_MinSelfDischgRates_12 : 27|10@1+ (0.1,0) [0|102.3] "%"  MBMU,PC
 SG_ S2A_S7_AvgSelfDischgRates_12 : 37|10@1+ (0.1,0) [0|102.3] "%"  MBMU,PC
 SG_ S2A_S7_Reserved_12 : 47|1@1+ (1,0) [0|1] ""  MBMU
 SG_ S2A_S7_SOH_12 : 48|16@1+ (0.1,0) [0|6553.5] ""  MBMU

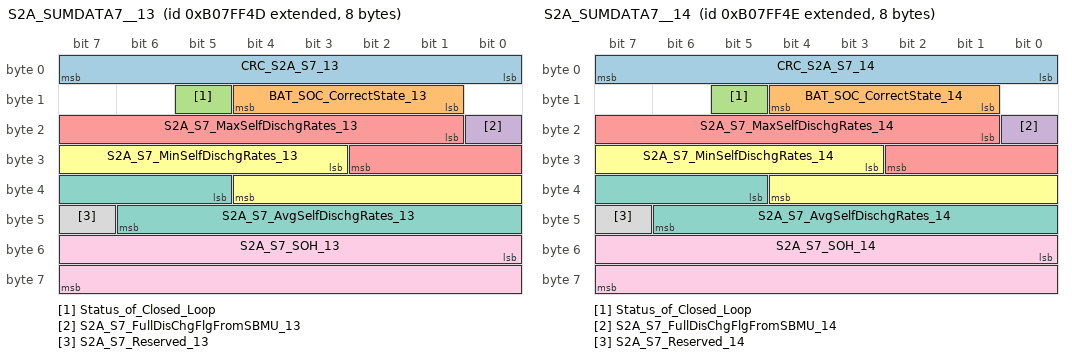
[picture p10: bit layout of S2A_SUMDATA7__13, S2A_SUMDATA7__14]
BO_ 2332557133 S2A_SUMDATA7__13: 8 SBMU
 SG_ CRC_S2A_S7_13 : 0|8@1+ (1,0) [0|255] ""  MBMU
 SG_ BAT_SOC_CorrectState_13 : 9|4@1+ (1,0) [0|15] ""  MBMU
 SG_ Status_of_Closed_Loop : 13|1@1+ (1,0) [0|1] ""  MBMU
 SG_ S2A_S7_FullDisChgFlgFromSBMU_13 : 16|1@1+ (1,0) [0|1] ""  MBMU
 SG_ S2A_S7_MaxSelfDischgRates_13 : 17|10@1+ (0.1,0) [0|102.3] "%"  MBMU,PC
 SG_ S2A_S7_MinSelfDischgRates_13 : 27|10@1+ (0.1,0) [0|102.3] "%"  MBMU,PC
 SG_ S2A_S7_AvgSelfDischgRates_13 : 37|10@1+ (0.1,0) [0|102.3] "%"  MBMU,PC
 SG_ S2A_S7_Reserved_13 : 47|1@1+ (1,0) [0|1] ""  MBMU
 SG_ S2A_S7_SOH_13 : 48|16@1+ (0.1,0) [0|6553.5] ""  MBMU

BO_ 2332557134 S2A_SUMDATA7__14: 8 SBMU
 SG_ CRC_S2A_S7_14 : 0|8@1+ (1,0) [0|255] ""  MBMU
 SG_ BAT_SOC_CorrectState_14 : 9|4@1+ (1,0) [0|15] ""  MBMU
 SG_ Status_of_Closed_Loop : 13|1@1+ (1,0) [0|1] ""  MBMU
 SG_ S2A_S7_FullDisChgFlgFromSBMU_14 : 16|1@1+ (1,0) [0|1] ""  MBMU
 SG_ S2A_S7_MaxSelfDischgRates_14 : 17|10@1+ (0.1,0) [0|102.3] "%"  MBMU,PC
 SG_ S2A_S7_MinSelfDischgRates_14 : 27|10@1+ (0.1,0) [0|102.3] "%"  MBMU,PC
 SG_ S2A_S7_AvgSelfDischgRates_14 : 37|10@1+ (0.1,0) [0|102.3] "%"  MBMU,PC
 SG_ S2A_S7_Reserved_14 : 47|1@1+ (1,0) [0|1] ""  MBMU
 SG_ S2A_S7_SOH_14 : 48|16@1+ (0.1,0) [0|6553.5] ""  MBMU

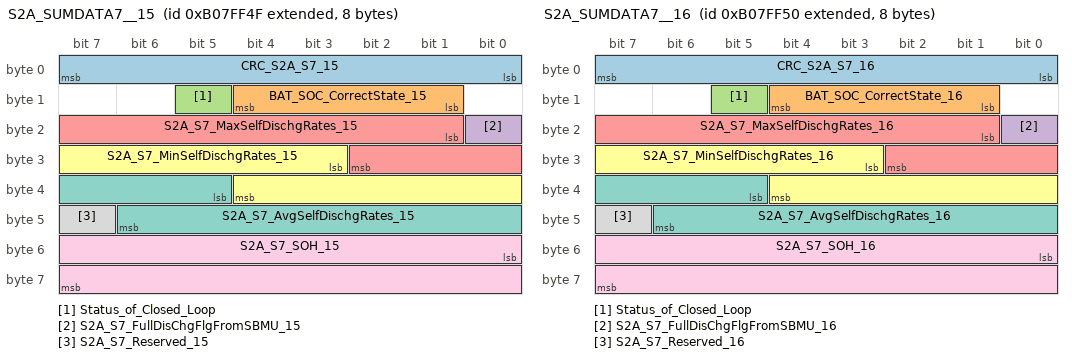
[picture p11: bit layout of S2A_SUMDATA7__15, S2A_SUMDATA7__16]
BO_ 2332557135 S2A_SUMDATA7__15: 8 SBMU
 SG_ CRC_S2A_S7_15 : 0|8@1+ (1,0) [0|255] ""  MBMU
 SG_ BAT_SOC_CorrectState_15 : 9|4@1+ (1,0) [0|15] ""  MBMU
 SG_ Status_of_Closed_Loop : 13|1@1+ (1,0) [0|1] ""  MBMU
 SG_ S2A_S7_FullDisChgFlgFromSBMU_15 : 16|1@1+ (1,0) [0|1] ""  MBMU
 SG_ S2A_S7_MaxSelfDischgRates_15 : 17|10@1+ (0.1,0) [0|102.3] "%"  MBMU,PC
 SG_ S2A_S7_MinSelfDischgRates_15 : 27|10@1+ (0.1,0) [0|102.3] "%"  MBMU,PC
 SG_ S2A_S7_AvgSelfDischgRates_15 : 37|10@1+ (0.1,0) [0|102.3] "%"  MBMU,PC
 SG_ S2A_S7_Reserved_15 : 47|1@1+ (1,0) [0|1] ""  MBMU
 SG_ S2A_S7_SOH_15 : 48|16@1+ (0.1,0) [0|6553.5] ""  MBMU

BO_ 2332557136 S2A_SUMDATA7__16: 8 SBMU
 SG_ CRC_S2A_S7_16 : 0|8@1+ (1,0) [0|255] ""  MBMU
 SG_ BAT_SOC_CorrectState_16 : 9|4@1+ (1,0) [0|15] ""  MBMU
 SG_ Status_of_Closed_Loop : 13|1@1+ (1,0) [0|1] ""  MBMU
 SG_ S2A_S7_FullDisChgFlgFromSBMU_16 : 16|1@1+ (1,0) [0|1] ""  MBMU
 SG_ S2A_S7_MaxSelfDischgRates_16 : 17|10@1+ (0.1,0) [0|102.3] "%"  MBMU,PC
 SG_ S2A_S7_MinSelfDischgRates_16 : 27|10@1+ (0.1,0) [0|102.3] "%"  MBMU,PC
 SG_ S2A_S7_AvgSelfDischgRates_16 : 37|10@1+ (0.1,0) [0|102.3] "%"  MBMU,PC
 SG_ S2A_S7_Reserved_16 : 47|1@1+ (1,0) [0|1] ""  MBMU
 SG_ S2A_S7_SOH_16 : 48|16@1+ (0.1,0) [0|6553.5] ""  MBMU

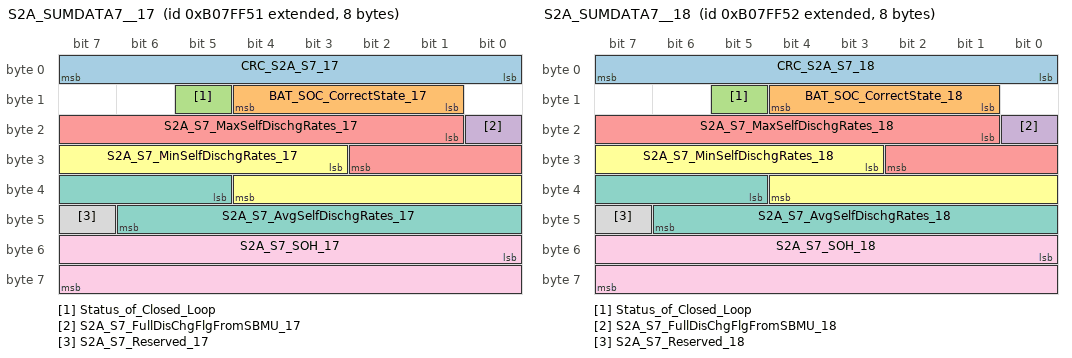
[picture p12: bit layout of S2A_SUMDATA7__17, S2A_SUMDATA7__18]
BO_ 2332557137 S2A_SUMDATA7__17: 8 SBMU
 SG_ CRC_S2A_S7_17 : 0|8@1+ (1,0) [0|255] ""  MBMU
 SG_ BAT_SOC_CorrectState_17 : 9|4@1+ (1,0) [0|15] ""  MBMU
 SG_ Status_of_Closed_Loop : 13|1@1+ (1,0) [0|1] ""  MBMU
 SG_ S2A_S7_FullDisChgFlgFromSBMU_17 : 16|1@1+ (1,0) [0|1] ""  MBMU
 SG_ S2A_S7_MaxSelfDischgRates_17 : 17|10@1+ (0.1,0) [0|102.3] "%"  MBMU,PC
 SG_ S2A_S7_MinSelfDischgRates_17 : 27|10@1+ (0.1,0) [0|102.3] "%"  MBMU,PC
 SG_ S2A_S7_AvgSelfDischgRates_17 : 37|10@1+ (0.1,0) [0|102.3] "%"  MBMU,PC
 SG_ S2A_S7_Reserved_17 : 47|1@1+ (1,0) [0|1] ""  MBMU
 SG_ S2A_S7_SOH_17 : 48|16@1+ (0.1,0) [0|6553.5] ""  MBMU

BO_ 2332557138 S2A_SUMDATA7__18: 8 SBMU
 SG_ CRC_S2A_S7_18 : 0|8@1+ (1,0) [0|255] ""  MBMU
 SG_ BAT_SOC_CorrectState_18 : 9|4@1+ (1,0) [0|15] ""  MBMU
 SG_ Status_of_Closed_Loop : 13|1@1+ (1,0) [0|1] ""  MBMU
 SG_ S2A_S7_FullDisChgFlgFromSBMU_18 : 16|1@1+ (1,0) [0|1] ""  MBMU
 SG_ S2A_S7_MaxSelfDischgRates_18 : 17|10@1+ (0.1,0) [0|102.3] "%"  MBMU,PC
 SG_ S2A_S7_MinSelfDischgRates_18 : 27|10@1+ (0.1,0) [0|102.3] "%"  MBMU,PC
 SG_ S2A_S7_AvgSelfDischgRates_18 : 37|10@1+ (0.1,0) [0|102.3] "%"  MBMU,PC
 SG_ S2A_S7_Reserved_18 : 47|1@1+ (1,0) [0|1] ""  MBMU
 SG_ S2A_S7_SOH_18 : 48|16@1+ (0.1,0) [0|6553.5] ""  MBMU

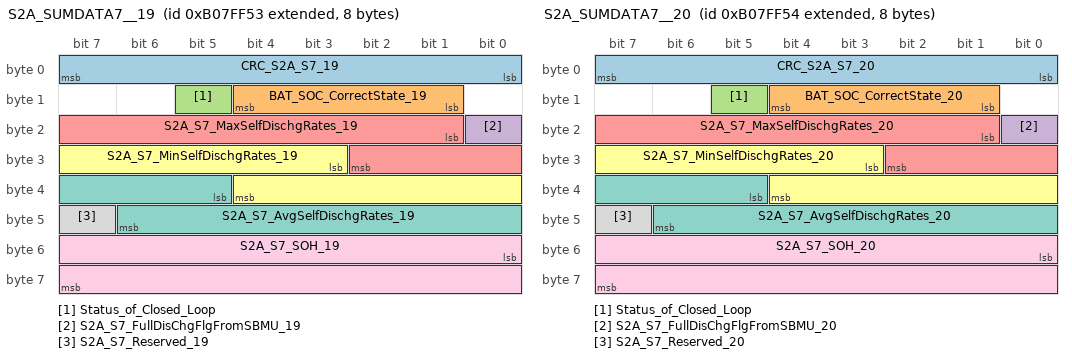
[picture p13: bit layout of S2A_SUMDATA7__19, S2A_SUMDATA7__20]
BO_ 2332557139 S2A_SUMDATA7__19: 8 SBMU
 SG_ CRC_S2A_S7_19 : 0|8@1+ (1,0) [0|255] ""  MBMU
 SG_ BAT_SOC_CorrectState_19 : 9|4@1+ (1,0) [0|15] ""  MBMU
 SG_ Status_of_Closed_Loop : 13|1@1+ (1,0) [0|1] ""  MBMU
 SG_ S2A_S7_FullDisChgFlgFromSBMU_19 : 16|1@1+ (1,0) [0|1] ""  MBMU
 SG_ S2A_S7_MaxSelfDischgRates_19 : 17|10@1+ (0.1,0) [0|102.3] "%"  MBMU,PC
 SG_ S2A_S7_MinSelfDischgRates_19 : 27|10@1+ (0.1,0) [0|102.3] "%"  MBMU,PC
 SG_ S2A_S7_AvgSelfDischgRates_19 : 37|10@1+ (0.1,0) [0|102.3] "%"  MBMU,PC
 SG_ S2A_S7_Reserved_19 : 47|1@1+ (1,0) [0|1] ""  MBMU
 SG_ S2A_S7_SOH_19 : 48|16@1+ (0.1,0) [0|6553.5] ""  MBMU

BO_ 2332557140 S2A_SUMDATA7__20: 8 SBMU
 SG_ CRC_S2A_S7_20 : 0|8@1+ (1,0) [0|255] ""  MBMU
 SG_ BAT_SOC_CorrectState_20 : 9|4@1+ (1,0) [0|15] ""  MBMU
 SG_ Status_of_Closed_Loop : 13|1@1+ (1,0) [0|1] ""  MBMU
 SG_ S2A_S7_FullDisChgFlgFromSBMU_20 : 16|1@1+ (1,0) [0|1] ""  MBMU
 SG_ S2A_S7_MaxSelfDischgRates_20 : 17|10@1+ (0.1,0) [0|102.3] "%"  MBMU,PC
 SG_ S2A_S7_MinSelfDischgRates_20 : 27|10@1+ (0.1,0) [0|102.3] "%"  MBMU,PC
 SG_ S2A_S7_AvgSelfDischgRates_20 : 37|10@1+ (0.1,0) [0|102.3] "%"  MBMU,PC
 SG_ S2A_S7_Reserved_20 : 47|1@1+ (1,0) [0|1] ""  MBMU
 SG_ S2A_S7_SOH_20 : 48|16@1+ (0.1,0) [0|6553.5] ""  MBMU

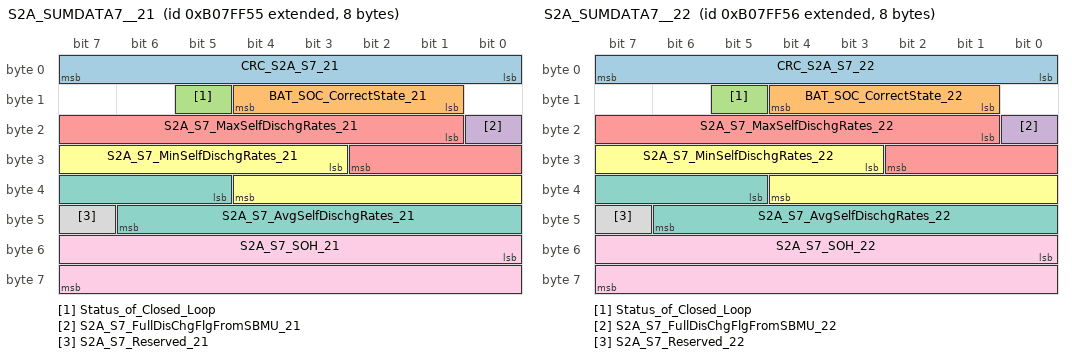
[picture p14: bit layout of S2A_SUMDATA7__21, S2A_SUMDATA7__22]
BO_ 2332557141 S2A_SUMDATA7__21: 8 SBMU
 SG_ CRC_S2A_S7_21 : 0|8@1+ (1,0) [0|255] ""  MBMU
 SG_ BAT_SOC_CorrectState_21 : 9|4@1+ (1,0) [0|15] ""  MBMU
 SG_ Status_of_Closed_Loop : 13|1@1+ (1,0) [0|1] ""  MBMU
 SG_ S2A_S7_FullDisChgFlgFromSBMU_21 : 16|1@1+ (1,0) [0|1] ""  MBMU
 SG_ S2A_S7_MaxSelfDischgRates_21 : 17|10@1+ (0.1,0) [0|102.3] "%"  MBMU,PC
 SG_ S2A_S7_MinSelfDischgRates_21 : 27|10@1+ (0.1,0) [0|102.3] "%"  MBMU,PC
 SG_ S2A_S7_AvgSelfDischgRates_21 : 37|10@1+ (0.1,0) [0|102.3] "%"  MBMU,PC
 SG_ S2A_S7_Reserved_21 : 47|1@1+ (1,0) [0|1] ""  MBMU
 SG_ S2A_S7_SOH_21 : 48|16@1+ (0.1,0) [0|6553.5] ""  MBMU

BO_ 2332557142 S2A_SUMDATA7__22: 8 SBMU
 SG_ CRC_S2A_S7_22 : 0|8@1+ (1,0) [0|255] ""  MBMU
 SG_ BAT_SOC_CorrectState_22 : 9|4@1+ (1,0) [0|15] ""  MBMU
 SG_ Status_of_Closed_Loop : 13|1@1+ (1,0) [0|1] ""  MBMU
 SG_ S2A_S7_FullDisChgFlgFromSBMU_22 : 16|1@1+ (1,0) [0|1] ""  MBMU
 SG_ S2A_S7_MaxSelfDischgRates_22 : 17|10@1+ (0.1,0) [0|102.3] "%"  MBMU,PC
 SG_ S2A_S7_MinSelfDischgRates_22 : 27|10@1+ (0.1,0) [0|102.3] "%"  MBMU,PC
 SG_ S2A_S7_AvgSelfDischgRates_22 : 37|10@1+ (0.1,0) [0|102.3] "%"  MBMU,PC
 SG_ S2A_S7_Reserved_22 : 47|1@1+ (1,0) [0|1] ""  MBMU
 SG_ S2A_S7_SOH_22 : 48|16@1+ (0.1,0) [0|6553.5] ""  MBMU

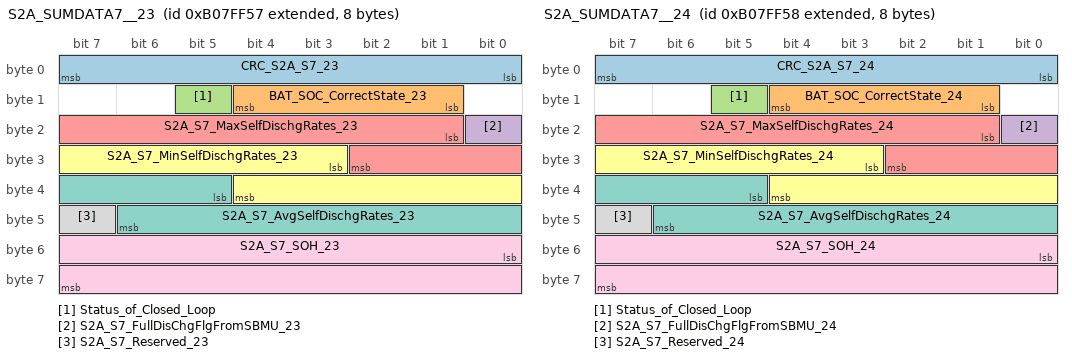
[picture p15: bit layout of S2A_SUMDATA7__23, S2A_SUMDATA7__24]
BO_ 2332557143 S2A_SUMDATA7__23: 8 SBMU
 SG_ CRC_S2A_S7_23 : 0|8@1+ (1,0) [0|255] ""  MBMU
 SG_ BAT_SOC_CorrectState_23 : 9|4@1+ (1,0) [0|15] ""  MBMU
 SG_ Status_of_Closed_Loop : 13|1@1+ (1,0) [0|1] ""  MBMU
 SG_ S2A_S7_FullDisChgFlgFromSBMU_23 : 16|1@1+ (1,0) [0|1] ""  MBMU
 SG_ S2A_S7_MaxSelfDischgRates_23 : 17|10@1+ (0.1,0) [0|102.3] "%"  MBMU,PC
 SG_ S2A_S7_MinSelfDischgRates_23 : 27|10@1+ (0.1,0) [0|102.3] "%"  MBMU,PC
 SG_ S2A_S7_AvgSelfDischgRates_23 : 37|10@1+ (0.1,0) [0|102.3] "%"  MBMU,PC
 SG_ S2A_S7_Reserved_23 : 47|1@1+ (1,0) [0|1] ""  MBMU
 SG_ S2A_S7_SOH_23 : 48|16@1+ (0.1,0) [0|6553.5] ""  MBMU

BO_ 2332557144 S2A_SUMDATA7__24: 8 SBMU
 SG_ CRC_S2A_S7_24 : 0|8@1+ (1,0) [0|255] ""  MBMU
 SG_ BAT_SOC_CorrectState_24 : 9|4@1+ (1,0) [0|15] ""  MBMU
 SG_ Status_of_Closed_Loop : 13|1@1+ (1,0) [0|1] ""  MBMU
 SG_ S2A_S7_FullDisChgFlgFromSBMU_24 : 16|1@1+ (1,0) [0|1] ""  MBMU
 SG_ S2A_S7_MaxSelfDischgRates_24 : 17|10@1+ (0.1,0) [0|102.3] "%"  MBMU,PC
 SG_ S2A_S7_MinSelfDischgRates_24 : 27|10@1+ (0.1,0) [0|102.3] "%"  MBMU,PC
 SG_ S2A_S7_AvgSelfDischgRates_24 : 37|10@1+ (0.1,0) [0|102.3] "%"  MBMU,PC
 SG_ S2A_S7_Reserved_24 : 47|1@1+ (1,0) [0|1] ""  MBMU
 SG_ S2A_S7_SOH_24 : 48|16@1+ (0.1,0) [0|6553.5] ""  MBMU

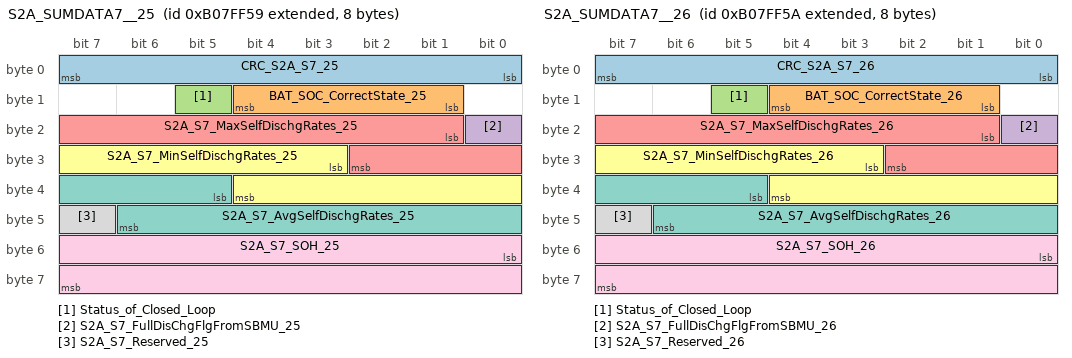
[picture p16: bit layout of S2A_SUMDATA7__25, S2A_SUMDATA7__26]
BO_ 2332557145 S2A_SUMDATA7__25: 8 SBMU
 SG_ CRC_S2A_S7_25 : 0|8@1+ (1,0) [0|255] ""  MBMU
 SG_ BAT_SOC_CorrectState_25 : 9|4@1+ (1,0) [0|15] ""  MBMU
 SG_ Status_of_Closed_Loop : 13|1@1+ (1,0) [0|1] ""  MBMU
 SG_ S2A_S7_FullDisChgFlgFromSBMU_25 : 16|1@1+ (1,0) [0|1] ""  MBMU
 SG_ S2A_S7_MaxSelfDischgRates_25 : 17|10@1+ (0.1,0) [0|102.3] "%"  MBMU,PC
 SG_ S2A_S7_MinSelfDischgRates_25 : 27|10@1+ (0.1,0) [0|102.3] "%"  MBMU,PC
 SG_ S2A_S7_AvgSelfDischgRates_25 : 37|10@1+ (0.1,0) [0|102.3] "%"  MBMU,PC
 SG_ S2A_S7_Reserved_25 : 47|1@1+ (1,0) [0|1] ""  MBMU
 SG_ S2A_S7_SOH_25 : 48|16@1+ (0.1,0) [0|6553.5] ""  MBMU

BO_ 2332557146 S2A_SUMDATA7__26: 8 SBMU
 SG_ CRC_S2A_S7_26 : 0|8@1+ (1,0) [0|255] ""  MBMU
 SG_ BAT_SOC_CorrectState_26 : 9|4@1+ (1,0) [0|15] ""  MBMU
 SG_ Status_of_Closed_Loop : 13|1@1+ (1,0) [0|1] ""  MBMU
 SG_ S2A_S7_FullDisChgFlgFromSBMU_26 : 16|1@1+ (1,0) [0|1] ""  MBMU
 SG_ S2A_S7_MaxSelfDischgRates_26 : 17|10@1+ (0.1,0) [0|102.3] "%"  MBMU,PC
 SG_ S2A_S7_MinSelfDischgRates_26 : 27|10@1+ (0.1,0) [0|102.3] "%"  MBMU,PC
 SG_ S2A_S7_AvgSelfDischgRates_26 : 37|10@1+ (0.1,0) [0|102.3] "%"  MBMU,PC
 SG_ S2A_S7_Reserved_26 : 47|1@1+ (1,0) [0|1] ""  MBMU
 SG_ S2A_S7_SOH_26 : 48|16@1+ (0.1,0) [0|6553.5] ""  MBMU

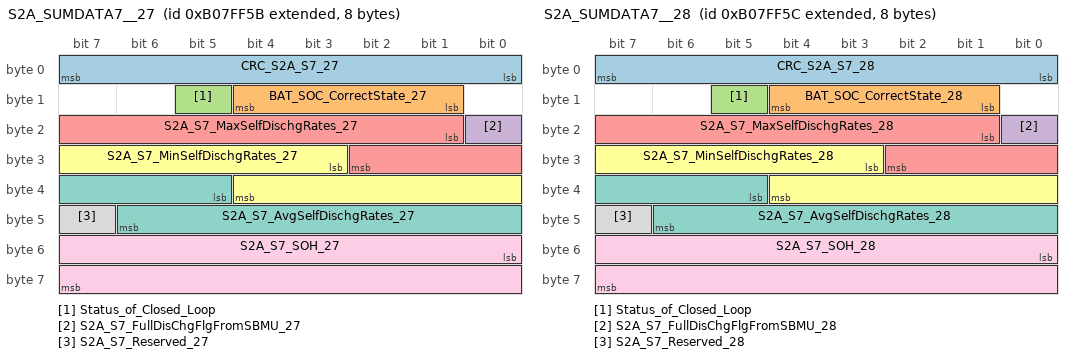
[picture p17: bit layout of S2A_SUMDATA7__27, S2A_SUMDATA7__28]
BO_ 2332557147 S2A_SUMDATA7__27: 8 SBMU
 SG_ CRC_S2A_S7_27 : 0|8@1+ (1,0) [0|255] ""  MBMU
 SG_ BAT_SOC_CorrectState_27 : 9|4@1+ (1,0) [0|15] ""  MBMU
 SG_ Status_of_Closed_Loop : 13|1@1+ (1,0) [0|1] ""  MBMU
 SG_ S2A_S7_FullDisChgFlgFromSBMU_27 : 16|1@1+ (1,0) [0|1] ""  MBMU
 SG_ S2A_S7_MaxSelfDischgRates_27 : 17|10@1+ (0.1,0) [0|102.3] "%"  MBMU,PC
 SG_ S2A_S7_MinSelfDischgRates_27 : 27|10@1+ (0.1,0) [0|102.3] "%"  MBMU,PC
 SG_ S2A_S7_AvgSelfDischgRates_27 : 37|10@1+ (0.1,0) [0|102.3] "%"  MBMU,PC
 SG_ S2A_S7_Reserved_27 : 47|1@1+ (1,0) [0|1] ""  MBMU
 SG_ S2A_S7_SOH_27 : 48|16@1+ (0.1,0) [0|6553.5] ""  MBMU

BO_ 2332557148 S2A_SUMDATA7__28: 8 SBMU
 SG_ CRC_S2A_S7_28 : 0|8@1+ (1,0) [0|255] ""  MBMU
 SG_ BAT_SOC_CorrectState_28 : 9|4@1+ (1,0) [0|15] ""  MBMU
 SG_ Status_of_Closed_Loop : 13|1@1+ (1,0) [0|1] ""  MBMU
 SG_ S2A_S7_FullDisChgFlgFromSBMU_28 : 16|1@1+ (1,0) [0|1] ""  MBMU
 SG_ S2A_S7_MaxSelfDischgRates_28 : 17|10@1+ (0.1,0) [0|102.3] "%"  MBMU,PC
 SG_ S2A_S7_MinSelfDischgRates_28 : 27|10@1+ (0.1,0) [0|102.3] "%"  MBMU,PC
 SG_ S2A_S7_AvgSelfDischgRates_28 : 37|10@1+ (0.1,0) [0|102.3] "%"  MBMU,PC
 SG_ S2A_S7_Reserved_28 : 47|1@1+ (1,0) [0|1] ""  MBMU
 SG_ S2A_S7_SOH_28 : 48|16@1+ (0.1,0) [0|6553.5] ""  MBMU

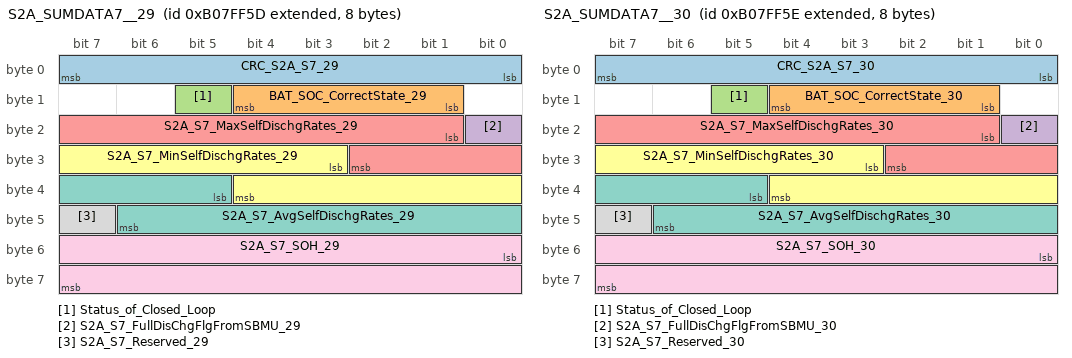
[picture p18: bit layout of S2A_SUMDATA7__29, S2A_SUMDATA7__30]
BO_ 2332557149 S2A_SUMDATA7__29: 8 SBMU
 SG_ CRC_S2A_S7_29 : 0|8@1+ (1,0) [0|255] ""  MBMU
 SG_ BAT_SOC_CorrectState_29 : 9|4@1+ (1,0) [0|15] ""  MBMU
 SG_ Status_of_Closed_Loop : 13|1@1+ (1,0) [0|1] ""  MBMU
 SG_ S2A_S7_FullDisChgFlgFromSBMU_29 : 16|1@1+ (1,0) [0|1] ""  MBMU
 SG_ S2A_S7_MaxSelfDischgRates_29 : 17|10@1+ (0.1,0) [0|102.3] "%"  MBMU,PC
 SG_ S2A_S7_MinSelfDischgRates_29 : 27|10@1+ (0.1,0) [0|102.3] "%"  MBMU,PC
 SG_ S2A_S7_AvgSelfDischgRates_29 : 37|10@1+ (0.1,0) [0|102.3] "%"  MBMU,PC
 SG_ S2A_S7_Reserved_29 : 47|1@1+ (1,0) [0|1] ""  MBMU
 SG_ S2A_S7_SOH_29 : 48|16@1+ (0.1,0) [0|6553.5] ""  MBMU

BO_ 2332557150 S2A_SUMDATA7__30: 8 SBMU
 SG_ CRC_S2A_S7_30 : 0|8@1+ (1,0) [0|255] ""  MBMU
 SG_ BAT_SOC_CorrectState_30 : 9|4@1+ (1,0) [0|15] ""  MBMU
 SG_ Status_of_Closed_Loop : 13|1@1+ (1,0) [0|1] ""  MBMU
 SG_ S2A_S7_FullDisChgFlgFromSBMU_30 : 16|1@1+ (1,0) [0|1] ""  MBMU
 SG_ S2A_S7_MaxSelfDischgRates_30 : 17|10@1+ (0.1,0) [0|102.3] "%"  MBMU,PC
 SG_ S2A_S7_MinSelfDischgRates_30 : 27|10@1+ (0.1,0) [0|102.3] "%"  MBMU,PC
 SG_ S2A_S7_AvgSelfDischgRates_30 : 37|10@1+ (0.1,0) [0|102.3] "%"  MBMU,PC
 SG_ S2A_S7_Reserved_30 : 47|1@1+ (1,0) [0|1] ""  MBMU
 SG_ S2A_S7_SOH_30 : 48|16@1+ (0.1,0) [0|6553.5] ""  MBMU

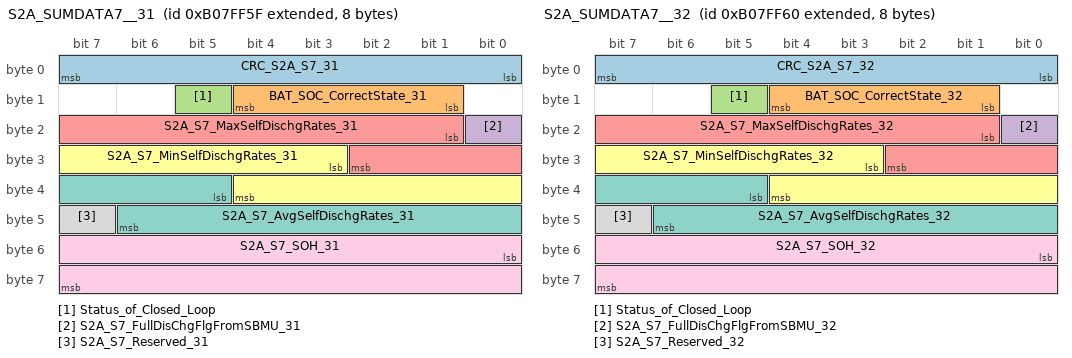
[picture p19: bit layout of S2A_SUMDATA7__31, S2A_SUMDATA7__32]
BO_ 2332557151 S2A_SUMDATA7__31: 8 SBMU
 SG_ CRC_S2A_S7_31 : 0|8@1+ (1,0) [0|255] ""  MBMU
 SG_ BAT_SOC_CorrectState_31 : 9|4@1+ (1,0) [0|15] ""  MBMU
 SG_ Status_of_Closed_Loop : 13|1@1+ (1,0) [0|1] ""  MBMU
 SG_ S2A_S7_FullDisChgFlgFromSBMU_31 : 16|1@1+ (1,0) [0|1] ""  MBMU
 SG_ S2A_S7_MaxSelfDischgRates_31 : 17|10@1+ (0.1,0) [0|102.3] "%"  MBMU,PC
 SG_ S2A_S7_MinSelfDischgRates_31 : 27|10@1+ (0.1,0) [0|102.3] "%"  MBMU,PC
 SG_ S2A_S7_AvgSelfDischgRates_31 : 37|10@1+ (0.1,0) [0|102.3] "%"  MBMU,PC
 SG_ S2A_S7_Reserved_31 : 47|1@1+ (1,0) [0|1] ""  MBMU
 SG_ S2A_S7_SOH_31 : 48|16@1+ (0.1,0) [0|6553.5] ""  MBMU

BO_ 2332557152 S2A_SUMDATA7__32: 8 SBMU
 SG_ CRC_S2A_S7_32 : 0|8@1+ (1,0) [0|255] ""  MBMU
 SG_ BAT_SOC_CorrectState_32 : 9|4@1+ (1,0) [0|15] ""  MBMU
 SG_ Status_of_Closed_Loop : 13|1@1+ (1,0) [0|1] ""  MBMU
 SG_ S2A_S7_FullDisChgFlgFromSBMU_32 : 16|1@1+ (1,0) [0|1] ""  MBMU
 SG_ S2A_S7_MaxSelfDischgRates_32 : 17|10@1+ (0.1,0) [0|102.3] "%"  MBMU,PC
 SG_ S2A_S7_MinSelfDischgRates_32 : 27|10@1+ (0.1,0) [0|102.3] "%"  MBMU,PC
 SG_ S2A_S7_AvgSelfDischgRates_32 : 37|10@1+ (0.1,0) [0|102.3] "%"  MBMU,PC
 SG_ S2A_S7_Reserved_32 : 47|1@1+ (1,0) [0|1] ""  MBMU
 SG_ S2A_S7_SOH_32 : 48|16@1+ (0.1,0) [0|6553.5] ""  MBMU

CM_ SG_ 2332360543 CRC_S2A_S4_31 "S2A概要数据4 的CRC";
CM_ SG_ 2332360543 BAT_Ucell_Avg_31 "平均单体电压";
CM_ SG_ 2332360543 BAT_T_Max_31 "最高单体温度";
CM_ SG_ 2332360543 BAT_T_Min_31 "最低单体温度";
CM_ SG_ 2332360543 BAT_T_Avg_31 "平均单体温度";
CM_ SG_ 2332360543 BAT_T_Max_CSC_31 "最高温度所在CSC号";
CM_ SG_ 2332360543 BAT_T_Min_CSC_31 "最低温度所在CSC号";
CM_ SG_ 2332360544 CRC_S2A_S4_32 "S2A概要数据4 的CRC";
CM_ SG_ 2332360544 BAT_Ucell_Avg_32 "平均单体电压";
CM_ SG_ 2332360544 BAT_T_Max_32 "最高单体温度";
CM_ SG_ 2332360544 BAT_T_Min_32 "最低单体温度";
CM_ SG_ 2332360544 BAT_T_Avg_32 "平均单体温度";
CM_ SG_ 2332360544 BAT_T_Max_CSC_32 "最高温度所在CSC号";
CM_ SG_ 2332360544 BAT_T_Min_CSC_32 "最低温度所在CSC号";
CM_ SG_ 2332360545 CRC_S2A_S4_33 "S2A概要数据4 的CRC";
CM_ SG_ 2332360545 BAT_Ucell_Avg_33 "平均单体电压";
CM_ SG_ 2332360545 BAT_T_Max_33 "最高单体温度";
CM_ SG_ 2332360545 BAT_T_Min_33 "最低单体温度";
CM_ SG_ 2332360545 BAT_T_Avg_33 "平均单体温度";
CM_ SG_ 2332360545 BAT_T_Max_CSC_33 "最高温度所在CSC号";
CM_ SG_ 2332360545 BAT_T_Min_CSC_33 "最低温度所在CSC号";
CM_ SG_ 2332360546 CRC_S2A_S4_34 "S2A概要数据4 的CRC";
CM_ SG_ 2332360546 BAT_Ucell_Avg_34 "平均单体电压";
CM_ SG_ 2332360546 BAT_T_Max_34 "最高单体温度";
CM_ SG_ 2332360546 BAT_T_Min_34 "最低单体温度";
CM_ SG_ 2332360546 BAT_T_Avg_34 "平均单体温度";
CM_ SG_ 2332360546 BAT_T_Max_CSC_34 "最高温度所在CSC号";
CM_ SG_ 2332360546 BAT_T_Min_CSC_34 "最低温度所在CSC号";
CM_ SG_ 2332360547 CRC_S2A_S4_35 "S2A概要数据4 的CRC";
CM_ SG_ 2332360547 BAT_Ucell_Avg_35 "平均单体电压";
CM_ SG_ 2332360547 BAT_T_Max_35 "最高单体温度";
CM_ SG_ 2332360547 BAT_T_Min_35 "最低单体温度";
CM_ SG_ 2332360547 BAT_T_Avg_35 "平均单体温度";
CM_ SG_ 2332360547 BAT_T_Max_CSC_35 "最高温度所在CSC号";
CM_ SG_ 2332360547 BAT_T_Min_CSC_35 "最低温度所在CSC号";
CM_ SG_ 2332360548 CRC_S2A_S4_36 "S2A概要数据4 的CRC";
CM_ SG_ 2332360548 BAT_Ucell_Avg_36 "平均单体电压";
CM_ SG_ 2332360548 BAT_T_Max_36 "最高单体温度";
CM_ SG_ 2332360548 BAT_T_Min_36 "最低单体温度";
CM_ SG_ 2332360548 BAT_T_Avg_36 "平均单体温度";
CM_ SG_ 2332360548 BAT_T_Max_CSC_36 "最高温度所在CSC号";
CM_ SG_ 2332360548 BAT_T_Min_CSC_36 "最低温度所在CSC号";
CM_ SG_ 2332360549 CRC_S2A_S4_37 "S2A概要数据4 的CRC";
CM_ SG_ 2332360549 BAT_Ucell_Avg_37 "平均单体电压";
CM_ SG_ 2332360549 BAT_T_Max_37 "最高单体温度";
CM_ SG_ 2332360549 BAT_T_Min_37 "最低单体温度";
CM_ SG_ 2332360549 BAT_T_Avg_37 "平均单体温度";
CM_ SG_ 2332360549 BAT_T_Max_CSC_37 "最高温度所在CSC号";
CM_ SG_ 2332360549 BAT_T_Min_CSC_37 "最低温度所在CSC号";
CM_ SG_ 2332360550 CRC_S2A_S4_38 "S2A概要数据4 的CRC";
CM_ SG_ 2332360550 BAT_Ucell_Avg_38 "平均单体电压";
CM_ SG_ 2332360550 BAT_T_Max_38 "最高单体温度";
CM_ SG_ 2332360550 BAT_T_Min_38 "最低单体温度";
CM_ SG_ 2332360550 BAT_T_Avg_38 "平均单体温度";
CM_ SG_ 2332360550 BAT_T_Max_CSC_38 "最高温度所在CSC号";
CM_ SG_ 2332360550 BAT_T_Min_CSC_38 "最低温度所在CSC号";
CM_ SG_ 2332360551 CRC_S2A_S4_39 "S2A概要数据4 的CRC";
CM_ SG_ 2332360551 BAT_Ucell_Avg_39 "平均单体电压";
CM_ SG_ 2332360551 BAT_T_Max_39 "最高单体温度";
CM_ SG_ 2332360551 BAT_T_Min_39 "最低单体温度";
CM_ SG_ 2332360551 BAT_T_Avg_39 "平均单体温度";
CM_ SG_ 2332360551 BAT_T_Max_CSC_39 "最高温度所在CSC号";
CM_ SG_ 2332360551 BAT_T_Min_CSC_39 "最低温度所在CSC号";
CM_ SG_ 2332360552 CRC_S2A_S4_40 "S2A概要数据4 的CRC";
CM_ SG_ 2332360552 BAT_Ucell_Avg_40 "平均单体电压";
CM_ SG_ 2332360552 BAT_T_Max_40 "最高单体温度";
CM_ SG_ 2332360552 BAT_T_Min_40 "最低单体温度";
CM_ SG_ 2332360552 BAT_T_Avg_40 "平均单体温度";
CM_ SG_ 2332360552 BAT_T_Max_CSC_40 "最高温度所在CSC号";
CM_ SG_ 2332360552 BAT_T_Min_CSC_40 "最低温度所在CSC号";
CM_ SG_ 2332360553 CRC_S2A_S4_41 "S2A概要数据4 的CRC";
CM_ SG_ 2332360553 BAT_Ucell_Avg_41 "平均单体电压";
CM_ SG_ 2332360553 BAT_T_Max_41 "最高单体温度";
CM_ SG_ 2332360553 BAT_T_Min_41 "最低单体温度";
CM_ SG_ 2332360553 BAT_T_Avg_41 "平均单体温度";
CM_ SG_ 2332360553 BAT_T_Max_CSC_41 "最高温度所在CSC号";
CM_ SG_ 2332360553 BAT_T_Min_CSC_41 "最低温度所在CSC号";
CM_ SG_ 2332360554 CRC_S2A_S4_42 "S2A概要数据4 的CRC";
CM_ SG_ 2332360554 BAT_Ucell_Avg_42 "平均单体电压";
CM_ SG_ 2332360554 BAT_T_Max_42 "最高单体温度";
CM_ SG_ 2332360554 BAT_T_Min_42 "最低单体温度";
CM_ SG_ 2332360554 BAT_T_Avg_42 "平均单体温度";
CM_ SG_ 2332360554 BAT_T_Max_CSC_42 "最高温度所在CSC号";
CM_ SG_ 2332360554 BAT_T_Min_CSC_42 "最低温度所在CSC号";
CM_ SG_ 2332360555 CRC_S2A_S4_43 "S2A概要数据4 的CRC";
CM_ SG_ 2332360555 BAT_Ucell_Avg_43 "平均单体电压";
CM_ SG_ 2332360555 BAT_T_Max_43 "最高单体温度";
CM_ SG_ 2332360555 BAT_T_Min_43 "最低单体温度";
CM_ SG_ 2332360555 BAT_T_Avg_43 "平均单体温度";
CM_ SG_ 2332360555 BAT_T_Max_CSC_43 "最高温度所在CSC号";
CM_ SG_ 2332360555 BAT_T_Min_CSC_43 "最低温度所在CSC号";
CM_ SG_ 2332360556 CRC_S2A_S4_44 "S2A概要数据4 的CRC";
CM_ SG_ 2332360556 BAT_Ucell_Avg_44 "平均单体电压";
CM_ SG_ 2332360556 BAT_T_Max_44 "最高单体温度";
CM_ SG_ 2332360556 BAT_T_Min_44 "最低单体温度";
CM_ SG_ 2332360556 BAT_T_Avg_44 "平均单体温度";
CM_ SG_ 2332360556 BAT_T_Max_CSC_44 "最高温度所在CSC号";
CM_ SG_ 2332360556 BAT_T_Min_CSC_44 "最低温度所在CSC号";
CM_ SG_ 2332360557 CRC_S2A_S4_45 "S2A概要数据4 的CRC";
CM_ SG_ 2332360557 BAT_Ucell_Avg_45 "平均单体电压";
CM_ SG_ 2332360557 BAT_T_Max_45 "最高单体温度";
CM_ SG_ 2332360557 BAT_T_Min_45 "最低单体温度";
CM_ SG_ 2332360557 BAT_T_Avg_45 "平均单体温度";
CM_ SG_ 2332360557 BAT_T_Max_CSC_45 "最高温度所在CSC号";
CM_ SG_ 2332360557 BAT_T_Min_CSC_45 "最低温度所在CSC号";
CM_ SG_ 2332360558 CRC_S2A_S4_46 "S2A概要数据4 的CRC";
CM_ SG_ 2332360558 BAT_Ucell_Avg_46 "平均单体电压";
CM_ SG_ 2332360558 BAT_T_Max_46 "最高单体温度";
CM_ SG_ 2332360558 BAT_T_Min_46 "最低单体温度";
CM_ SG_ 2332360558 BAT_T_Avg_46 "平均单体温度";
CM_ SG_ 2332360558 BAT_T_Max_CSC_46 "最高温度所在CSC号";
CM_ SG_ 2332360558 BAT_T_Min_CSC_46 "最低温度所在CSC号";
CM_ SG_ 2332360559 CRC_S2A_S4_47 "S2A概要数据4 的CRC";
CM_ SG_ 2332360559 BAT_Ucell_Avg_47 "平均单体电压";
CM_ SG_ 2332360559 BAT_T_Max_47 "最高单体温度";
CM_ SG_ 2332360559 BAT_T_Min_47 "最低单体温度";
CM_ SG_ 2332360559 BAT_T_Avg_47 "平均单体温度";
CM_ SG_ 2332360559 BAT_T_Max_CSC_47 "最高温度所在CSC号";
CM_ SG_ 2332360559 BAT_T_Min_CSC_47 "最低温度所在CSC号";
CM_ SG_ 2332360560 CRC_S2A_S4_48 "S2A概要数据4 的CRC";
CM_ SG_ 2332360560 BAT_Ucell_Avg_48 "平均单体电压";
CM_ SG_ 2332360560 BAT_T_Max_48 "最高单体温度";
CM_ SG_ 2332360560 BAT_T_Min_48 "最低单体温度";
CM_ SG_ 2332360560 BAT_T_Avg_48 "平均单体温度";
CM_ SG_ 2332360560 BAT_T_Max_CSC_48 "最高温度所在CSC号";
CM_ SG_ 2332360560 BAT_T_Min_CSC_48 "最低温度所在CSC号";
CM_ SG_ 2332360561 CRC_S2A_S4_49 "S2A概要数据4 的CRC";
CM_ SG_ 2332360561 BAT_Ucell_Avg_49 "平均单体电压";
CM_ SG_ 2332360561 BAT_T_Max_49 "最高单体温度";
CM_ SG_ 2332360561 BAT_T_Min_49 "最低单体温度";
CM_ SG_ 2332360561 BAT_T_Avg_49 "平均单体温度";
CM_ SG_ 2332360561 BAT_T_Max_CSC_49 "最高温度所在CSC号";
CM_ SG_ 2332360561 BAT_T_Min_CSC_49 "最低温度所在CSC号";
CM_ SG_ 2332360562 CRC_S2A_S4_50 "S2A概要数据4 的CRC";
CM_ SG_ 2332360562 BAT_Ucell_Avg_50 "平均单体电压";
CM_ SG_ 2332360562 BAT_T_Max_50 "最高单体温度";
CM_ SG_ 2332360562 BAT_T_Min_50 "最低单体温度";
CM_ SG_ 2332360562 BAT_T_Avg_50 "平均单体温度";
CM_ SG_ 2332360562 BAT_T_Max_CSC_50 "最高温度所在CSC号";
CM_ SG_ 2332360562 BAT_T_Min_CSC_50 "最低温度所在CSC号";
CM_ SG_ 2332360563 CRC_S2A_S4_51 "S2A概要数据4 的CRC";
CM_ SG_ 2332360563 BAT_Ucell_Avg_51 "平均单体电压";
CM_ SG_ 2332360563 BAT_T_Max_51 "最高单体温度";
CM_ SG_ 2332360563 BAT_T_Min_51 "最低单体温度";
CM_ SG_ 2332360563 BAT_T_Avg_51 "平均单体温度";
CM_ SG_ 2332360563 BAT_T_Max_CSC_51 "最高温度所在CSC号";
CM_ SG_ 2332360563 BAT_T_Min_CSC_51 "最低温度所在CSC号";
CM_ SG_ 2332360564 CRC_S2A_S4_52 "S2A概要数据4 的CRC";
CM_ SG_ 2332360564 BAT_Ucell_Avg_52 "平均单体电压";
CM_ SG_ 2332360564 BAT_T_Max_52 "最高单体温度";
CM_ SG_ 2332360564 BAT_T_Min_52 "最低单体温度";
CM_ SG_ 2332360564 BAT_T_Avg_52 "平均单体温度";
CM_ SG_ 2332360564 BAT_T_Max_CSC_52 "最高温度所在CSC号";
CM_ SG_ 2332360564 BAT_T_Min_CSC_52 "最低温度所在CSC号";
CM_ SG_ 2332360565 CRC_S2A_S4_53 "S2A概要数据4 的CRC";
CM_ SG_ 2332360565 BAT_Ucell_Avg_53 "平均单体电压";
CM_ SG_ 2332360565 BAT_T_Max_53 "最高单体温度";
CM_ SG_ 2332360565 BAT_T_Min_53 "最低单体温度";
CM_ SG_ 2332360565 BAT_T_Avg_53 "平均单体温度";
CM_ SG_ 2332360565 BAT_T_Max_CSC_53 "最高温度所在CSC号";
CM_ SG_ 2332360565 BAT_T_Min_CSC_53 "最低温度所在CSC号";
CM_ SG_ 2332360566 CRC_S2A_S4_54 "S2A概要数据4 的CRC";
CM_ SG_ 2332360566 BAT_Ucell_Avg_54 "平均单体电压";
CM_ SG_ 2332360566 BAT_T_Max_54 "最高单体温度";
CM_ SG_ 2332360566 BAT_T_Min_54 "最低单体温度";
CM_ SG_ 2332360566 BAT_T_Avg_54 "平均单体温度";
CM_ SG_ 2332360566 BAT_T_Max_CSC_54 "最高温度所在CSC号";
CM_ SG_ 2332360566 BAT_T_Min_CSC_54 "最低温度所在CSC号";
CM_ SG_ 2332360567 CRC_S2A_S4_55 "S2A概要数据4 的CRC";
CM_ SG_ 2332360567 BAT_Ucell_Avg_55 "平均单体电压";
CM_ SG_ 2332360567 BAT_T_Max_55 "最高单体温度";
CM_ SG_ 2332360567 BAT_T_Min_55 "最低单体温度";
CM_ SG_ 2332360567 BAT_T_Avg_55 "平均单体温度";
CM_ SG_ 2332360567 BAT_T_Max_CSC_55 "最高温度所在CSC号";
CM_ SG_ 2332360567 BAT_T_Min_CSC_55 "最低温度所在CSC号";
CM_ SG_ 2332360568 CRC_S2A_S4_56 "S2A概要数据4 的CRC";
CM_ SG_ 2332360568 BAT_Ucell_Avg_56 "平均单体电压";
CM_ SG_ 2332360568 BAT_T_Max_56 "最高单体温度";
CM_ SG_ 2332360568 BAT_T_Min_56 "最低单体温度";
CM_ SG_ 2332360568 BAT_T_Avg_56 "平均单体温度";
CM_ SG_ 2332360568 BAT_T_Max_CSC_56 "最高温度所在CSC号";
CM_ SG_ 2332360568 BAT_T_Min_CSC_56 "最低温度所在CSC号";
CM_ SG_ 2332360569 CRC_S2A_S4_57 "S2A概要数据4 的CRC";
CM_ SG_ 2332360569 BAT_Ucell_Avg_57 "平均单体电压";
CM_ SG_ 2332360569 BAT_T_Max_57 "最高单体温度";
CM_ SG_ 2332360569 BAT_T_Min_57 "最低单体温度";
CM_ SG_ 2332360569 BAT_T_Avg_57 "平均单体温度";
CM_ SG_ 2332360569 BAT_T_Max_CSC_57 "最高温度所在CSC号";
CM_ SG_ 2332360569 BAT_T_Min_CSC_57 "最低温度所在CSC号";
CM_ SG_ 2332360570 CRC_S2A_S4_58 "S2A概要数据4 的CRC";
CM_ SG_ 2332360570 BAT_Ucell_Avg_58 "平均单体电压";
CM_ SG_ 2332360570 BAT_T_Max_58 "最高单体温度";
CM_ SG_ 2332360570 BAT_T_Min_58 "最低单体温度";
CM_ SG_ 2332360570 BAT_T_Avg_58 "平均单体温度";
CM_ SG_ 2332360570 BAT_T_Max_CSC_58 "最高温度所在CSC号";
CM_ SG_ 2332360570 BAT_T_Min_CSC_58 "最低温度所在CSC号";
CM_ SG_ 2332360571 CRC_S2A_S4_59 "S2A概要数据4 的CRC";
CM_ SG_ 2332360571 BAT_Ucell_Avg_59 "平均单体电压";
CM_ SG_ 2332360571 BAT_T_Max_59 "最高单体温度";
CM_ SG_ 2332360571 BAT_T_Min_59 "最低单体温度";
CM_ SG_ 2332360571 BAT_T_Avg_59 "平均单体温度";
CM_ SG_ 2332360571 BAT_T_Max_CSC_59 "最高温度所在CSC号";
CM_ SG_ 2332360571 BAT_T_Min_CSC_59 "最低温度所在CSC号";
CM_ SG_ 2332360572 CRC_S2A_S4_60 "S2A概要数据4 的CRC";
CM_ SG_ 2332360572 BAT_Ucell_Avg_60 "平均单体电压";
CM_ SG_ 2332360572 BAT_T_Max_60 "最高单体温度";
CM_ SG_ 2332360572 BAT_T_Min_60 "最低单体温度";
CM_ SG_ 2332360572 BAT_T_Avg_60 "平均单体温度";
CM_ SG_ 2332360572 BAT_T_Max_CSC_60 "最高温度所在CSC号";
CM_ SG_ 2332360572 BAT_T_Min_CSC_60 "最低温度所在CSC号";
CM_ SG_ 2332360573 CRC_S2A_S4_61 "S2A概要数据4 的CRC";
CM_ SG_ 2332360573 BAT_Ucell_Avg_61 "平均单体电压";
CM_ SG_ 2332360573 BAT_T_Max_61 "最高单体温度";
CM_ SG_ 2332360573 BAT_T_Min_61 "最低单体温度";
CM_ SG_ 2332360573 BAT_T_Avg_61 "平均单体温度";
CM_ SG_ 2332360573 BAT_T_Max_CSC_61 "最高温度所在CSC号";
CM_ SG_ 2332360573 BAT_T_Min_CSC_61 "最低温度所在CSC号";
CM_ SG_ 2332360574 CRC_S2A_S4_62 "S2A概要数据4 的CRC";
CM_ SG_ 2332360574 BAT_Ucell_Avg_62 "平均单体电压";
CM_ SG_ 2332360574 BAT_T_Max_62 "最高单体温度";
CM_ SG_ 2332360574 BAT_T_Min_62 "最低单体温度";
CM_ SG_ 2332360574 BAT_T_Avg_62 "平均单体温度";
CM_ SG_ 2332360574 BAT_T_Max_CSC_62 "最高温度所在CSC号";
CM_ SG_ 2332360574 BAT_T_Min_CSC_62 "最低温度所在CSC号";
CM_ SG_ 2332360575 CRC_S2A_S4_63 "S2A概要数据4 的CRC";
CM_ SG_ 2332360575 BAT_Ucell_Avg_63 "平均单体电压";
CM_ SG_ 2332360575 BAT_T_Max_63 "最高单体温度";
CM_ SG_ 2332360575 BAT_T_Min_63 "最低单体温度";
CM_ SG_ 2332360575 BAT_T_Avg_63 "平均单体温度";
CM_ SG_ 2332360575 BAT_T_Max_CSC_63 "最高温度所在CSC号";
CM_ SG_ 2332360575 BAT_T_Min_CSC_63 "最低温度所在CSC号";
CM_ SG_ 2332426049 CRC_S2A_S5_01 "S2A概要数据5 的CRC";
CM_ SG_ 2332426049 BAT_SOH_HVS_01 "显示SOH";
CM_ SG_ 2332426049 BAT_SOC_HVS_01 "真实SOC";
CM_ SG_ 2332426049 BAT_User_SOC_HVS_01 "显示SOC";
CM_ SG_ 2332426049 BAT_Cell_Max_SOC_HVS_01 "单柜最大SOC";
CM_ SG_ 2332426049 BAT_Cell_Min_SOC_HVS_01 "单柜最小SOC";
CM_ SG_ 2332426049 BAT_Cool_CellBalStat_01 "冷调均衡模式状态反馈";
CM_ SG_ 2332426049 BAT_CorrectState_Require "Rack静置维护模式请求";
CM_ SG_ 2332426050 CRC_S2A_S5_02 "S2A概要数据5 的CRC";
CM_ SG_ 2332426050 BAT_SOH_HVS_02 "显示SOH";
CM_ SG_ 2332426050 BAT_SOC_HVS_02 "真实SOC";
CM_ SG_ 2332426050 BAT_User_SOC_HVS_02 "显示SOC";
CM_ SG_ 2332426050 BAT_Cell_Max_SOC_HVS_02 "单柜最大SOC";
CM_ SG_ 2332426050 BAT_Cell_Min_SOC_HVS_02 "单柜最小SOC";
CM_ SG_ 2332426050 BAT_Cool_CellBalStat_02 "冷调均衡模式状态反馈";
CM_ SG_ 2332426050 BAT_CorrectState_Require "Rack静置维护模式请求";
CM_ SG_ 2332426051 CRC_S2A_S5_03 "S2A概要数据5 的CRC";
CM_ SG_ 2332426051 BAT_SOH_HVS_03 "显示SOH";
CM_ SG_ 2332426051 BAT_SOC_HVS_03 "真实SOC";
CM_ SG_ 2332426051 BAT_User_SOC_HVS_03 "显示SOC";
CM_ SG_ 2332426051 BAT_Cell_Max_SOC_HVS_03 "单柜最大SOC";
CM_ SG_ 2332426051 BAT_Cell_Min_SOC_HVS_03 "单柜最小SOC";
CM_ SG_ 2332426051 BAT_Cool_CellBalStat_03 "冷调均衡模式状态反馈";
CM_ SG_ 2332426051 BAT_CorrectState_Require "Rack静置维护模式请求";
CM_ SG_ 2332426052 CRC_S2A_S5_04 "S2A概要数据5 的CRC";
CM_ SG_ 2332426052 BAT_SOH_HVS_04 "显示SOH";
CM_ SG_ 2332426052 BAT_SOC_HVS_04 "真实SOC";
CM_ SG_ 2332426052 BAT_User_SOC_HVS_04 "显示SOC";
CM_ SG_ 2332426052 BAT_Cell_Max_SOC_HVS_04 "单柜最大SOC";
CM_ SG_ 2332426052 BAT_Cell_Min_SOC_HVS_04 "单柜最小SOC";
CM_ SG_ 2332426052 BAT_Cool_CellBalStat_04 "冷调均衡模式状态反馈";
CM_ SG_ 2332426052 BAT_CorrectState_Require "Rack静置维护模式请求";
CM_ SG_ 2332426053 CRC_S2A_S5_05 "S2A概要数据5 的CRC";
CM_ SG_ 2332426053 BAT_SOH_HVS_05 "显示SOH";
CM_ SG_ 2332426053 BAT_SOC_HVS_05 "真实SOC";
CM_ SG_ 2332426053 BAT_User_SOC_HVS_05 "显示SOC";
CM_ SG_ 2332426053 BAT_Cell_Max_SOC_HVS_05 "单柜最大SOC";
CM_ SG_ 2332426053 BAT_Cell_Min_SOC_HVS_05 "单柜最小SOC";
CM_ SG_ 2332426053 BAT_Cool_CellBalStat_05 "冷调均衡模式状态反馈";
CM_ SG_ 2332426053 BAT_CorrectState_Require "Rack静置维护模式请求";
CM_ SG_ 2332426054 CRC_S2A_S5_06 "S2A概要数据5 的CRC";
CM_ SG_ 2332426054 BAT_SOH_HVS_06 "显示SOH";
CM_ SG_ 2332426054 BAT_SOC_HVS_06 "真实SOC";
CM_ SG_ 2332426054 BAT_User_SOC_HVS_06 "显示SOC";
CM_ SG_ 2332426054 BAT_Cell_Max_SOC_HVS_06 "单柜最大SOC";
CM_ SG_ 2332426054 BAT_Cell_Min_SOC_HVS_06 "单柜最小SOC";
CM_ SG_ 2332426054 BAT_Cool_CellBalStat_06 "冷调均衡模式状态反馈";
CM_ SG_ 2332426054 BAT_CorrectState_Require "Rack静置维护模式请求";
CM_ SG_ 2332426055 CRC_S2A_S5_07 "S2A概要数据5 的CRC";
CM_ SG_ 2332426055 BAT_SOH_HVS_07 "显示SOH";
CM_ SG_ 2332426055 BAT_SOC_HVS_07 "真实SOC";
CM_ SG_ 2332426055 BAT_User_SOC_HVS_07 "显示SOC";
CM_ SG_ 2332426055 BAT_Cell_Max_SOC_HVS_07 "单柜最大SOC";
CM_ SG_ 2332426055 BAT_Cell_Min_SOC_HVS_07 "单柜最小SOC";
CM_ SG_ 2332426055 BAT_Cool_CellBalStat_07 "冷调均衡模式状态反馈";
CM_ SG_ 2332426055 BAT_CorrectState_Require "Rack静置维护模式请求";
CM_ SG_ 2332426056 CRC_S2A_S5_08 "S2A概要数据5 的CRC";
CM_ SG_ 2332426056 BAT_SOH_HVS_08 "显示SOH";
CM_ SG_ 2332426056 BAT_SOC_HVS_08 "真实SOC";
CM_ SG_ 2332426056 BAT_User_SOC_HVS_08 "显示SOC";
CM_ SG_ 2332426056 BAT_Cell_Max_SOC_HVS_08 "单柜最大SOC";
CM_ SG_ 2332426056 BAT_Cell_Min_SOC_HVS_08 "单柜最小SOC";
CM_ SG_ 2332426056 BAT_Cool_CellBalStat_08 "冷调均衡模式状态反馈";
CM_ SG_ 2332426056 BAT_CorrectState_Require "Rack静置维护模式请求";
CM_ SG_ 2332426057 CRC_S2A_S5_09 "S2A概要数据5 的CRC";
CM_ SG_ 2332426057 BAT_SOH_HVS_09 "显示SOH";
CM_ SG_ 2332426057 BAT_SOC_HVS_09 "真实SOC";
CM_ SG_ 2332426057 BAT_User_SOC_HVS_09 "显示SOC";
CM_ SG_ 2332426057 BAT_Cell_Max_SOC_HVS_09 "单柜最大SOC";
CM_ SG_ 2332426057 BAT_Cell_Min_SOC_HVS_09 "单柜最小SOC";
CM_ SG_ 2332426057 BAT_Cool_CellBalStat_09 "冷调均衡模式状态反馈";
CM_ SG_ 2332426057 BAT_CorrectState_Require "Rack静置维护模式请求";
CM_ SG_ 2332426058 CRC_S2A_S5_10 "S2A概要数据5 的CRC";
CM_ SG_ 2332426058 BAT_SOH_HVS_10 "显示SOH";
CM_ SG_ 2332426058 BAT_SOC_HVS_10 "真实SOC";
CM_ SG_ 2332426058 BAT_User_SOC_HVS_10 "显示SOC";
CM_ SG_ 2332426058 BAT_Cell_Max_SOC_HVS_10 "单柜最大SOC";
CM_ SG_ 2332426058 BAT_Cell_Min_SOC_HVS_10 "单柜最小SOC";
CM_ SG_ 2332426058 BAT_Cool_CellBalStat_10 "冷调均衡模式状态反馈";
CM_ SG_ 2332426058 BAT_CorrectState_Require "Rack静置维护模式请求";
CM_ SG_ 2332426059 CRC_S2A_S5_11 "S2A概要数据5 的CRC";
CM_ SG_ 2332426059 BAT_SOH_HVS_11 "显示SOH";
CM_ SG_ 2332426059 BAT_SOC_HVS_11 "真实SOC";
CM_ SG_ 2332426059 BAT_User_SOC_HVS_11 "显示SOC";
CM_ SG_ 2332426059 BAT_Cell_Max_SOC_HVS_11 "单柜最大SOC";
CM_ SG_ 2332426059 BAT_Cell_Min_SOC_HVS_11 "单柜最小SOC";
CM_ SG_ 2332426059 BAT_Cool_CellBalStat_11 "冷调均衡模式状态反馈";
CM_ SG_ 2332426059 BAT_CorrectState_Require "Rack静置维护模式请求";
CM_ SG_ 2332426060 CRC_S2A_S5_12 "S2A概要数据5 的CRC";
CM_ SG_ 2332426060 BAT_SOH_HVS_12 "显示SOH";
CM_ SG_ 2332426060 BAT_SOC_HVS_12 "真实SOC";
CM_ SG_ 2332426060 BAT_User_SOC_HVS_12 "显示SOC";
CM_ SG_ 2332426060 BAT_Cell_Max_SOC_HVS_12 "单柜最大SOC";
CM_ SG_ 2332426060 BAT_Cell_Min_SOC_HVS_12 "单柜最小SOC";
CM_ SG_ 2332426060 BAT_Cool_CellBalStat_12 "冷调均衡模式状态反馈";
CM_ SG_ 2332426060 BAT_CorrectState_Require "Rack静置维护模式请求";
CM_ SG_ 2332426061 CRC_S2A_S5_13 "S2A概要数据5 的CRC";
CM_ SG_ 2332426061 BAT_SOH_HVS_13 "显示SOH";
CM_ SG_ 2332426061 BAT_SOC_HVS_13 "真实SOC";
CM_ SG_ 2332426061 BAT_User_SOC_HVS_13 "显示SOC";
CM_ SG_ 2332426061 BAT_Cell_Max_SOC_HVS_13 "单柜最大SOC";
CM_ SG_ 2332426061 BAT_Cell_Min_SOC_HVS_13 "单柜最小SOC";
CM_ SG_ 2332426061 BAT_Cool_CellBalStat_13 "冷调均衡模式状态反馈";
CM_ SG_ 2332426061 BAT_CorrectState_Require "Rack静置维护模式请求";
CM_ SG_ 2332426062 CRC_S2A_S5_14 "S2A概要数据5 的CRC";
CM_ SG_ 2332426062 BAT_SOH_HVS_14 "显示SOH";
CM_ SG_ 2332426062 BAT_SOC_HVS_14 "真实SOC";
CM_ SG_ 2332426062 BAT_User_SOC_HVS_14 "显示SOC";
CM_ SG_ 2332426062 BAT_Cell_Max_SOC_HVS_14 "单柜最大SOC";
CM_ SG_ 2332426062 BAT_Cell_Min_SOC_HVS_14 "单柜最小SOC";
CM_ SG_ 2332426062 BAT_Cool_CellBalStat_14 "冷调均衡模式状态反馈";
CM_ SG_ 2332426062 BAT_CorrectState_Require "Rack静置维护模式请求";
CM_ SG_ 2332426063 CRC_S2A_S5_15 "S2A概要数据5 的CRC";
CM_ SG_ 2332426063 BAT_SOH_HVS_15 "显示SOH";
CM_ SG_ 2332426063 BAT_SOC_HVS_15 "真实SOC";
CM_ SG_ 2332426063 BAT_User_SOC_HVS_15 "显示SOC";
CM_ SG_ 2332426063 BAT_Cell_Max_SOC_HVS_15 "单柜最大SOC";
CM_ SG_ 2332426063 BAT_Cell_Min_SOC_HVS_15 "单柜最小SOC";
CM_ SG_ 2332426063 BAT_Cool_CellBalStat_15 "冷调均衡模式状态反馈";
CM_ SG_ 2332426063 BAT_CorrectState_Require "Rack静置维护模式请求";
CM_ SG_ 2332426064 CRC_S2A_S5_16 "S2A概要数据5 的CRC";
CM_ SG_ 2332426064 BAT_SOH_HVS_16 "显示SOH";
CM_ SG_ 2332426064 BAT_SOC_HVS_16 "真实SOC";
CM_ SG_ 2332426064 BAT_User_SOC_HVS_16 "显示SOC";
CM_ SG_ 2332426064 BAT_Cell_Max_SOC_HVS_16 "单柜最大SOC";
CM_ SG_ 2332426064 BAT_Cell_Min_SOC_HVS_16 "单柜最小SOC";
CM_ SG_ 2332426064 BAT_Cool_CellBalStat_16 "冷调均衡模式状态反馈";
CM_ SG_ 2332426064 BAT_CorrectState_Require "Rack静置维护模式请求";
CM_ SG_ 2332426065 CRC_S2A_S5_17 "S2A概要数据5 的CRC";
CM_ SG_ 2332426065 BAT_SOH_HVS_17 "显示SOH";
CM_ SG_ 2332426065 BAT_SOC_HVS_17 "真实SOC";
CM_ SG_ 2332426065 BAT_User_SOC_HVS_17 "显示SOC";
CM_ SG_ 2332426065 BAT_Cell_Max_SOC_HVS_17 "单柜最大SOC";
CM_ SG_ 2332426065 BAT_Cell_Min_SOC_HVS_17 "单柜最小SOC";
CM_ SG_ 2332426065 BAT_Cool_CellBalStat_17 "冷调均衡模式状态反馈";
CM_ SG_ 2332426065 BAT_CorrectState_Require "Rack静置维护模式请求";
CM_ SG_ 2332426066 CRC_S2A_S5_18 "S2A概要数据5 的CRC";
CM_ SG_ 2332426066 BAT_SOH_HVS_18 "显示SOH";
CM_ SG_ 2332426066 BAT_SOC_HVS_18 "真实SOC";
CM_ SG_ 2332426066 BAT_User_SOC_HVS_18 "显示SOC";
CM_ SG_ 2332426066 BAT_Cell_Max_SOC_HVS_18 "单柜最大SOC";
CM_ SG_ 2332426066 BAT_Cell_Min_SOC_HVS_18 "单柜最小SOC";
CM_ SG_ 2332426066 BAT_Cool_CellBalStat_18 "冷调均衡模式状态反馈";
CM_ SG_ 2332426066 BAT_CorrectState_Require "Rack静置维护模式请求";
CM_ SG_ 2332426067 CRC_S2A_S5_19 "S2A概要数据5 的CRC";
CM_ SG_ 2332426067 BAT_SOH_HVS_19 "显示SOH";
CM_ SG_ 2332426067 BAT_SOC_HVS_19 "真实SOC";
CM_ SG_ 2332426067 BAT_User_SOC_HVS_19 "显示SOC";
CM_ SG_ 2332426067 BAT_Cell_Max_SOC_HVS_19 "单柜最大SOC";
CM_ SG_ 2332426067 BAT_Cell_Min_SOC_HVS_19 "单柜最小SOC";
CM_ SG_ 2332426067 BAT_Cool_CellBalStat_19 "冷调均衡模式状态反馈";
CM_ SG_ 2332426067 BAT_CorrectState_Require "Rack静置维护模式请求";
CM_ SG_ 2332426068 CRC_S2A_S5_20 "S2A概要数据5 的CRC";
CM_ SG_ 2332426068 BAT_SOH_HVS_20 "显示SOH";
CM_ SG_ 2332426068 BAT_SOC_HVS_20 "真实SOC";
CM_ SG_ 2332426068 BAT_User_SOC_HVS_20 "显示SOC";
CM_ SG_ 2332426068 BAT_Cell_Max_SOC_HVS_20 "单柜最大SOC";
CM_ SG_ 2332426068 BAT_Cell_Min_SOC_HVS_20 "单柜最小SOC";
CM_ SG_ 2332426068 BAT_Cool_CellBalStat_20 "冷调均衡模式状态反馈";
CM_ SG_ 2332426068 BAT_CorrectState_Require "Rack静置维护模式请求";
CM_ SG_ 2332426069 CRC_S2A_S5_21 "S2A概要数据5 的CRC";
CM_ SG_ 2332426069 BAT_SOH_HVS_21 "显示SOH";
CM_ SG_ 2332426069 BAT_SOC_HVS_21 "真实SOC";
CM_ SG_ 2332426069 BAT_User_SOC_HVS_21 "显示SOC";
CM_ SG_ 2332426069 BAT_Cell_Max_SOC_HVS_21 "单柜最大SOC";
CM_ SG_ 2332426069 BAT_Cell_Min_SOC_HVS_21 "单柜最小SOC";
CM_ SG_ 2332426069 BAT_Cool_CellBalStat_21 "冷调均衡模式状态反馈";
CM_ SG_ 2332426069 BAT_CorrectState_Require "Rack静置维护模式请求";
CM_ SG_ 2332426070 CRC_S2A_S5_22 "S2A概要数据5 的CRC";
CM_ SG_ 2332426070 BAT_SOH_HVS_22 "显示SOH";
CM_ SG_ 2332426070 BAT_SOC_HVS_22 "真实SOC";
CM_ SG_ 2332426070 BAT_User_SOC_HVS_22 "显示SOC";
CM_ SG_ 2332426070 BAT_Cell_Max_SOC_HVS_22 "单柜最大SOC";
CM_ SG_ 2332426070 BAT_Cell_Min_SOC_HVS_22 "单柜最小SOC";
CM_ SG_ 2332426070 BAT_Cool_CellBalStat_22 "冷调均衡模式状态反馈";
CM_ SG_ 2332426070 BAT_CorrectState_Require "Rack静置维护模式请求";
CM_ SG_ 2332426071 CRC_S2A_S5_23 "S2A概要数据5 的CRC";
CM_ SG_ 2332426071 BAT_SOH_HVS_23 "显示SOH";
CM_ SG_ 2332426071 BAT_SOC_HVS_23 "真实SOC";
CM_ SG_ 2332426071 BAT_User_SOC_HVS_23 "显示SOC";
CM_ SG_ 2332426071 BAT_Cell_Max_SOC_HVS_23 "单柜最大SOC";
CM_ SG_ 2332426071 BAT_Cell_Min_SOC_HVS_23 "单柜最小SOC";
CM_ SG_ 2332426071 BAT_Cool_CellBalStat_23 "冷调均衡模式状态反馈";
CM_ SG_ 2332426071 BAT_CorrectState_Require "Rack静置维护模式请求";
CM_ SG_ 2332426072 CRC_S2A_S5_24 "S2A概要数据5 的CRC";
CM_ SG_ 2332426072 BAT_SOH_HVS_24 "显示SOH";
CM_ SG_ 2332426072 BAT_SOC_HVS_24 "真实SOC";
CM_ SG_ 2332426072 BAT_User_SOC_HVS_24 "显示SOC";
CM_ SG_ 2332426072 BAT_Cell_Max_SOC_HVS_24 "单柜最大SOC";
CM_ SG_ 2332426072 BAT_Cell_Min_SOC_HVS_24 "单柜最小SOC";
CM_ SG_ 2332426072 BAT_Cool_CellBalStat_24 "冷调均衡模式状态反馈";
CM_ SG_ 2332426072 BAT_CorrectState_Require "Rack静置维护模式请求";
CM_ SG_ 2332426073 CRC_S2A_S5_25 "S2A概要数据5 的CRC";
CM_ SG_ 2332426073 BAT_SOH_HVS_25 "显示SOH";
CM_ SG_ 2332426073 BAT_SOC_HVS_25 "真实SOC";
CM_ SG_ 2332426073 BAT_User_SOC_HVS_25 "显示SOC";
CM_ SG_ 2332426073 BAT_Cell_Max_SOC_HVS_25 "单柜最大SOC";
CM_ SG_ 2332426073 BAT_Cell_Min_SOC_HVS_25 "单柜最小SOC";
CM_ SG_ 2332426073 BAT_Cool_CellBalStat_25 "冷调均衡模式状态反馈";
CM_ SG_ 2332426073 BAT_CorrectState_Require "Rack静置维护模式请求";
CM_ SG_ 2332426074 CRC_S2A_S5_26 "S2A概要数据5 的CRC";
CM_ SG_ 2332426074 BAT_SOH_HVS_26 "显示SOH";
CM_ SG_ 2332426074 BAT_SOC_HVS_26 "真实SOC";
CM_ SG_ 2332426074 BAT_User_SOC_HVS_26 "显示SOC";
CM_ SG_ 2332426074 BAT_Cell_Max_SOC_HVS_26 "单柜最大SOC";
CM_ SG_ 2332426074 BAT_Cell_Min_SOC_HVS_26 "单柜最小SOC";
CM_ SG_ 2332426074 BAT_Cool_CellBalStat_26 "冷调均衡模式状态反馈";
CM_ SG_ 2332426074 BAT_CorrectState_Require "Rack静置维护模式请求";
CM_ SG_ 2332426075 CRC_S2A_S5_27 "S2A概要数据5 的CRC";
CM_ SG_ 2332426075 BAT_SOH_HVS_27 "显示SOH";
CM_ SG_ 2332426075 BAT_SOC_HVS_27 "真实SOC";
CM_ SG_ 2332426075 BAT_User_SOC_HVS_27 "显示SOC";
CM_ SG_ 2332426075 BAT_Cell_Max_SOC_HVS_27 "单柜最大SOC";
CM_ SG_ 2332426075 BAT_Cell_Min_SOC_HVS_27 "单柜最小SOC";
CM_ SG_ 2332426075 BAT_Cool_CellBalStat_27 "冷调均衡模式状态反馈";
CM_ SG_ 2332426075 BAT_CorrectState_Require "Rack静置维护模式请求";
CM_ SG_ 2332426076 CRC_S2A_S5_28 "S2A概要数据5 的CRC";
CM_ SG_ 2332426076 BAT_SOH_HVS_28 "显示SOH";
CM_ SG_ 2332426076 BAT_SOC_HVS_28 "真实SOC";
CM_ SG_ 2332426076 BAT_User_SOC_HVS_28 "显示SOC";
CM_ SG_ 2332426076 BAT_Cell_Max_SOC_HVS_28 "单柜最大SOC";
CM_ SG_ 2332426076 BAT_Cell_Min_SOC_HVS_28 "单柜最小SOC";
CM_ SG_ 2332426076 BAT_Cool_CellBalStat_28 "冷调均衡模式状态反馈";
CM_ SG_ 2332426076 BAT_CorrectState_Require "Rack静置维护模式请求";
CM_ SG_ 2332426077 CRC_S2A_S5_29 "S2A概要数据5 的CRC";
CM_ SG_ 2332426077 BAT_SOH_HVS_29 "显示SOH";
CM_ SG_ 2332426077 BAT_SOC_HVS_29 "真实SOC";
CM_ SG_ 2332426077 BAT_User_SOC_HVS_29 "显示SOC";
CM_ SG_ 2332426077 BAT_Cell_Max_SOC_HVS_29 "单柜最大SOC";
CM_ SG_ 2332426077 BAT_Cell_Min_SOC_HVS_29 "单柜最小SOC";
CM_ SG_ 2332426077 BAT_Cool_CellBalStat_29 "冷调均衡模式状态反馈";
CM_ SG_ 2332426077 BAT_CorrectState_Require "Rack静置维护模式请求";
CM_ SG_ 2332426078 CRC_S2A_S5_30 "S2A概要数据5 的CRC";
CM_ SG_ 2332426078 BAT_SOH_HVS_30 "显示SOH";
CM_ SG_ 2332426078 BAT_SOC_HVS_30 "真实SOC";
CM_ SG_ 2332426078 BAT_User_SOC_HVS_30 "显示SOC";
CM_ SG_ 2332426078 BAT_Cell_Max_SOC_HVS_30 "单柜最大SOC";
CM_ SG_ 2332426078 BAT_Cell_Min_SOC_HVS_30 "单柜最小SOC";
CM_ SG_ 2332426078 BAT_Cool_CellBalStat_30 "冷调均衡模式状态反馈";
CM_ SG_ 2332426078 BAT_CorrectState_Require "Rack静置维护模式请求";
CM_ SG_ 2332426079 CRC_S2A_S5_31 "S2A概要数据5 的CRC";
CM_ SG_ 2332426079 BAT_SOH_HVS_31 "显示SOH";
CM_ SG_ 2332426079 BAT_SOC_HVS_31 "真实SOC";
CM_ SG_ 2332426079 BAT_User_SOC_HVS_31 "显示SOC";
CM_ SG_ 2332426079 BAT_Cell_Max_SOC_HVS_31 "单柜最大SOC";
CM_ SG_ 2332426079 BAT_Cell_Min_SOC_HVS_31 "单柜最小SOC";
CM_ SG_ 2332426079 BAT_Cool_CellBalStat_31 "冷调均衡模式状态反馈";
CM_ SG_ 2332426079 BAT_CorrectState_Require "Rack静置维护模式请求";
CM_ SG_ 2332426080 CRC_S2A_S5_32 "S2A概要数据5 的CRC";
CM_ SG_ 2332426080 BAT_SOH_HVS_32 "显示SOH";
CM_ SG_ 2332426080 BAT_SOC_HVS_32 "真实SOC";
CM_ SG_ 2332426080 BAT_User_SOC_HVS_32 "显示SOC";
CM_ SG_ 2332426080 BAT_Cell_Max_SOC_HVS_32 "单柜最大SOC";
CM_ SG_ 2332426080 BAT_Cell_Min_SOC_HVS_32 "单柜最小SOC";
CM_ SG_ 2332426080 BAT_Cool_CellBalStat_32 "冷调均衡模式状态反馈";
CM_ SG_ 2332426080 BAT_CorrectState_Require "Rack静置维护模式请求";
CM_ SG_ 2332426081 CRC_S2A_S5_33 "S2A概要数据5 的CRC";
CM_ SG_ 2332426081 BAT_SOH_HVS_33 "显示SOH";
CM_ SG_ 2332426081 BAT_SOC_HVS_33 "真实SOC";
CM_ SG_ 2332426081 BAT_User_SOC_HVS_33 "显示SOC";
CM_ SG_ 2332426081 BAT_Cell_Max_SOC_HVS_33 "单柜最大SOC";
CM_ SG_ 2332426081 BAT_Cell_Min_SOC_HVS_33 "单柜最小SOC";
CM_ SG_ 2332426081 BAT_Cool_CellBalStat_33 "冷调均衡模式状态反馈";
CM_ SG_ 2332426081 BAT_CorrectState_Require "Rack静置维护模式请求";
CM_ SG_ 2332426082 CRC_S2A_S5_34 "S2A概要数据5 的CRC";
CM_ SG_ 2332426082 BAT_SOH_HVS_34 "显示SOH";
CM_ SG_ 2332426082 BAT_SOC_HVS_34 "真实SOC";
CM_ SG_ 2332426082 BAT_User_SOC_HVS_34 "显示SOC";
CM_ SG_ 2332426082 BAT_Cell_Max_SOC_HVS_34 "单柜最大SOC";
CM_ SG_ 2332426082 BAT_Cell_Min_SOC_HVS_34 "单柜最小SOC";
CM_ SG_ 2332426082 BAT_Cool_CellBalStat_34 "冷调均衡模式状态反馈";
CM_ SG_ 2332426082 BAT_CorrectState_Require "Rack静置维护模式请求";
CM_ SG_ 2332426083 CRC_S2A_S5_35 "S2A概要数据5 的CRC";
CM_ SG_ 2332426083 BAT_SOH_HVS_35 "显示SOH";
CM_ SG_ 2332426083 BAT_SOC_HVS_35 "真实SOC";
CM_ SG_ 2332426083 BAT_User_SOC_HVS_35 "显示SOC";
CM_ SG_ 2332426083 BAT_Cell_Max_SOC_HVS_35 "单柜最大SOC";
CM_ SG_ 2332426083 BAT_Cell_Min_SOC_HVS_35 "单柜最小SOC";
CM_ SG_ 2332426083 BAT_Cool_CellBalStat_35 "冷调均衡模式状态反馈";
CM_ SG_ 2332426083 BAT_CorrectState_Require "Rack静置维护模式请求";
CM_ SG_ 2332426084 CRC_S2A_S5_36 "S2A概要数据5 的CRC";
CM_ SG_ 2332426084 BAT_SOH_HVS_36 "显示SOH";
CM_ SG_ 2332426084 BAT_SOC_HVS_36 "真实SOC";
CM_ SG_ 2332426084 BAT_User_SOC_HVS_36 "显示SOC";
CM_ SG_ 2332426084 BAT_Cell_Max_SOC_HVS_36 "单柜最大SOC";
CM_ SG_ 2332426084 BAT_Cell_Min_SOC_HVS_36 "单柜最小SOC";
CM_ SG_ 2332426084 BAT_Cool_CellBalStat_36 "冷调均衡模式状态反馈";
CM_ SG_ 2332426084 BAT_CorrectState_Require "Rack静置维护模式请求";
CM_ SG_ 2332426085 CRC_S2A_S5_37 "S2A概要数据5 的CRC";
CM_ SG_ 2332426085 BAT_SOH_HVS_37 "显示SOH";
CM_ SG_ 2332426085 BAT_SOC_HVS_37 "真实SOC";
CM_ SG_ 2332426085 BAT_User_SOC_HVS_37 "显示SOC";
CM_ SG_ 2332426085 BAT_Cell_Max_SOC_HVS_37 "单柜最大SOC";
CM_ SG_ 2332426085 BAT_Cell_Min_SOC_HVS_37 "单柜最小SOC";
CM_ SG_ 2332426085 BAT_Cool_CellBalStat_37 "冷调均衡模式状态反馈";
CM_ SG_ 2332426085 BAT_CorrectState_Require "Rack静置维护模式请求";
CM_ SG_ 2332426086 CRC_S2A_S5_38 "S2A概要数据5 的CRC";
CM_ SG_ 2332426086 BAT_SOH_HVS_38 "显示SOH";
CM_ SG_ 2332426086 BAT_SOC_HVS_38 "真实SOC";
CM_ SG_ 2332426086 BAT_User_SOC_HVS_38 "显示SOC";
CM_ SG_ 2332426086 BAT_Cell_Max_SOC_HVS_38 "单柜最大SOC";
CM_ SG_ 2332426086 BAT_Cell_Min_SOC_HVS_38 "单柜最小SOC";
CM_ SG_ 2332426086 BAT_Cool_CellBalStat_38 "冷调均衡模式状态反馈";
CM_ SG_ 2332426086 BAT_CorrectState_Require "Rack静置维护模式请求";
CM_ SG_ 2332426087 CRC_S2A_S5_39 "S2A概要数据5 的CRC";
CM_ SG_ 2332426087 BAT_SOH_HVS_39 "显示SOH";
CM_ SG_ 2332426087 BAT_SOC_HVS_39 "真实SOC";
CM_ SG_ 2332426087 BAT_User_SOC_HVS_39 "显示SOC";
CM_ SG_ 2332426087 BAT_Cell_Max_SOC_HVS_39 "单柜最大SOC";
CM_ SG_ 2332426087 BAT_Cell_Min_SOC_HVS_39 "单柜最小SOC";
CM_ SG_ 2332426087 BAT_Cool_CellBalStat_39 "冷调均衡模式状态反馈";
CM_ SG_ 2332426087 BAT_CorrectState_Require "Rack静置维护模式请求";
CM_ SG_ 2332426088 CRC_S2A_S5_40 "S2A概要数据5 的CRC";
CM_ SG_ 2332426088 BAT_SOH_HVS_40 "显示SOH";
CM_ SG_ 2332426088 BAT_SOC_HVS_40 "真实SOC";
CM_ SG_ 2332426088 BAT_User_SOC_HVS_40 "显示SOC";
CM_ SG_ 2332426088 BAT_Cell_Max_SOC_HVS_40 "单柜最大SOC";
CM_ SG_ 2332426088 BAT_Cell_Min_SOC_HVS_40 "单柜最小SOC";
CM_ SG_ 2332426088 BAT_Cool_CellBalStat_40 "冷调均衡模式状态反馈";
CM_ SG_ 2332426088 BAT_CorrectState_Require "Rack静置维护模式请求";
CM_ SG_ 2332426089 CRC_S2A_S5_41 "S2A概要数据5 的CRC";
CM_ SG_ 2332426089 BAT_SOH_HVS_41 "显示SOH";
CM_ SG_ 2332426089 BAT_SOC_HVS_41 "真实SOC";
CM_ SG_ 2332426089 BAT_User_SOC_HVS_41 "显示SOC";
CM_ SG_ 2332426089 BAT_Cell_Max_SOC_HVS_41 "单柜最大SOC";
CM_ SG_ 2332426089 BAT_Cell_Min_SOC_HVS_41 "单柜最小SOC";
CM_ SG_ 2332426089 BAT_Cool_CellBalStat_41 "冷调均衡模式状态反馈";
CM_ SG_ 2332426089 BAT_CorrectState_Require "Rack静置维护模式请求";
CM_ SG_ 2332426090 CRC_S2A_S5_42 "S2A概要数据5 的CRC";
CM_ SG_ 2332426090 BAT_SOH_HVS_42 "显示SOH";
CM_ SG_ 2332426090 BAT_SOC_HVS_42 "真实SOC";
CM_ SG_ 2332426090 BAT_User_SOC_HVS_42 "显示SOC";
CM_ SG_ 2332426090 BAT_Cell_Max_SOC_HVS_42 "单柜最大SOC";
CM_ SG_ 2332426090 BAT_Cell_Min_SOC_HVS_42 "单柜最小SOC";
CM_ SG_ 2332426090 BAT_Cool_CellBalStat_42 "冷调均衡模式状态反馈";
CM_ SG_ 2332426090 BAT_CorrectState_Require "Rack静置维护模式请求";
CM_ SG_ 2332426091 CRC_S2A_S5_43 "S2A概要数据5 的CRC";
CM_ SG_ 2332426091 BAT_SOH_HVS_43 "显示SOH";
CM_ SG_ 2332426091 BAT_SOC_HVS_43 "真实SOC";
CM_ SG_ 2332426091 BAT_User_SOC_HVS_43 "显示SOC";
CM_ SG_ 2332426091 BAT_Cell_Max_SOC_HVS_43 "单柜最大SOC";
CM_ SG_ 2332426091 BAT_Cell_Min_SOC_HVS_43 "单柜最小SOC";
CM_ SG_ 2332426091 BAT_Cool_CellBalStat_43 "冷调均衡模式状态反馈";
CM_ SG_ 2332426091 BAT_CorrectState_Require "Rack静置维护模式请求";
CM_ SG_ 2332426092 CRC_S2A_S5_44 "S2A概要数据5 的CRC";
CM_ SG_ 2332426092 BAT_SOH_HVS_44 "显示SOH";
CM_ SG_ 2332426092 BAT_SOC_HVS_44 "真实SOC";
CM_ SG_ 2332426092 BAT_User_SOC_HVS_44 "显示SOC";
CM_ SG_ 2332426092 BAT_Cell_Max_SOC_HVS_44 "单柜最大SOC";
CM_ SG_ 2332426092 BAT_Cell_Min_SOC_HVS_44 "单柜最小SOC";
CM_ SG_ 2332426092 BAT_Cool_CellBalStat_44 "冷调均衡模式状态反馈";
CM_ SG_ 2332426092 BAT_CorrectState_Require "Rack静置维护模式请求";
CM_ SG_ 2332426093 CRC_S2A_S5_45 "S2A概要数据5 的CRC";
CM_ SG_ 2332426093 BAT_SOH_HVS_45 "显示SOH";
CM_ SG_ 2332426093 BAT_SOC_HVS_45 "真实SOC";
CM_ SG_ 2332426093 BAT_User_SOC_HVS_45 "显示SOC";
CM_ SG_ 2332426093 BAT_Cell_Max_SOC_HVS_45 "单柜最大SOC";
CM_ SG_ 2332426093 BAT_Cell_Min_SOC_HVS_45 "单柜最小SOC";
CM_ SG_ 2332426093 BAT_Cool_CellBalStat_45 "冷调均衡模式状态反馈";
CM_ SG_ 2332426093 BAT_CorrectState_Require "Rack静置维护模式请求";
CM_ SG_ 2332426094 CRC_S2A_S5_46 "S2A概要数据5 的CRC";
CM_ SG_ 2332426094 BAT_SOH_HVS_46 "显示SOH";
CM_ SG_ 2332426094 BAT_SOC_HVS_46 "真实SOC";
CM_ SG_ 2332426094 BAT_User_SOC_HVS_46 "显示SOC";
CM_ SG_ 2332426094 BAT_Cell_Max_SOC_HVS_46 "单柜最大SOC";
CM_ SG_ 2332426094 BAT_Cell_Min_SOC_HVS_46 "单柜最小SOC";
CM_ SG_ 2332426094 BAT_Cool_CellBalStat_46 "冷调均衡模式状态反馈";
CM_ SG_ 2332426094 BAT_CorrectState_Require "Rack静置维护模式请求";
CM_ SG_ 2332426095 CRC_S2A_S5_47 "S2A概要数据5 的CRC";
CM_ SG_ 2332426095 BAT_SOH_HVS_47 "显示SOH";
CM_ SG_ 2332426095 BAT_SOC_HVS_47 "真实SOC";
CM_ SG_ 2332426095 BAT_User_SOC_HVS_47 "显示SOC";
CM_ SG_ 2332426095 BAT_Cell_Max_SOC_HVS_47 "单柜最大SOC";
CM_ SG_ 2332426095 BAT_Cell_Min_SOC_HVS_47 "单柜最小SOC";
CM_ SG_ 2332426095 BAT_Cool_CellBalStat_47 "冷调均衡模式状态反馈";
CM_ SG_ 2332426095 BAT_CorrectState_Require "Rack静置维护模式请求";
CM_ SG_ 2332426096 CRC_S2A_S5_48 "S2A概要数据5 的CRC";
CM_ SG_ 2332426096 BAT_SOH_HVS_48 "显示SOH";
CM_ SG_ 2332426096 BAT_SOC_HVS_48 "真实SOC";
CM_ SG_ 2332426096 BAT_User_SOC_HVS_48 "显示SOC";
CM_ SG_ 2332426096 BAT_Cell_Max_SOC_HVS_48 "单柜最大SOC";
CM_ SG_ 2332426096 BAT_Cell_Min_SOC_HVS_48 "单柜最小SOC";
CM_ SG_ 2332426096 BAT_Cool_CellBalStat_48 "冷调均衡模式状态反馈";
CM_ SG_ 2332426096 BAT_CorrectState_Require "Rack静置维护模式请求";
CM_ SG_ 2332426097 CRC_S2A_S5_49 "S2A概要数据5 的CRC";
CM_ SG_ 2332426097 BAT_SOH_HVS_49 "显示SOH";
CM_ SG_ 2332426097 BAT_SOC_HVS_49 "真实SOC";
CM_ SG_ 2332426097 BAT_User_SOC_HVS_49 "显示SOC";
CM_ SG_ 2332426097 BAT_Cell_Max_SOC_HVS_49 "单柜最大SOC";
CM_ SG_ 2332426097 BAT_Cell_Min_SOC_HVS_49 "单柜最小SOC";
CM_ SG_ 2332426097 BAT_Cool_CellBalStat_49 "冷调均衡模式状态反馈";
CM_ SG_ 2332426097 BAT_CorrectState_Require "Rack静置维护模式请求";
CM_ SG_ 2332426098 CRC_S2A_S5_50 "S2A概要数据5 的CRC";
CM_ SG_ 2332426098 BAT_SOH_HVS_50 "显示SOH";
CM_ SG_ 2332426098 BAT_SOC_HVS_50 "真实SOC";
CM_ SG_ 2332426098 BAT_User_SOC_HVS_50 "显示SOC";
CM_ SG_ 2332426098 BAT_Cell_Max_SOC_HVS_50 "单柜最大SOC";
CM_ SG_ 2332426098 BAT_Cell_Min_SOC_HVS_50 "单柜最小SOC";
CM_ SG_ 2332426098 BAT_Cool_CellBalStat_50 "冷调均衡模式状态反馈";
CM_ SG_ 2332426098 BAT_CorrectState_Require "Rack静置维护模式请求";
CM_ SG_ 2332426099 CRC_S2A_S5_51 "S2A概要数据5 的CRC";
CM_ SG_ 2332426099 BAT_SOH_HVS_51 "显示SOH";
CM_ SG_ 2332426099 BAT_SOC_HVS_51 "真实SOC";
CM_ SG_ 2332426099 BAT_User_SOC_HVS_51 "显示SOC";
CM_ SG_ 2332426099 BAT_Cell_Max_SOC_HVS_51 "单柜最大SOC";
CM_ SG_ 2332426099 BAT_Cell_Min_SOC_HVS_51 "单柜最小SOC";
CM_ SG_ 2332426099 BAT_Cool_CellBalStat_51 "冷调均衡模式状态反馈";
CM_ SG_ 2332426099 BAT_CorrectState_Require "Rack静置维护模式请求";
CM_ SG_ 2332426100 CRC_S2A_S5_52 "S2A概要数据5 的CRC";
CM_ SG_ 2332426100 BAT_SOH_HVS_52 "显示SOH";
CM_ SG_ 2332426100 BAT_SOC_HVS_52 "真实SOC";
CM_ SG_ 2332426100 BAT_User_SOC_HVS_52 "显示SOC";
CM_ SG_ 2332426100 BAT_Cell_Max_SOC_HVS_52 "单柜最大SOC";
CM_ SG_ 2332426100 BAT_Cell_Min_SOC_HVS_52 "单柜最小SOC";
CM_ SG_ 2332426100 BAT_Cool_CellBalStat_52 "冷调均衡模式状态反馈";
CM_ SG_ 2332426100 BAT_CorrectState_Require "Rack静置维护模式请求";
CM_ SG_ 2332426101 CRC_S2A_S5_53 "S2A概要数据5 的CRC";
CM_ SG_ 2332426101 BAT_SOH_HVS_53 "显示SOH";
CM_ SG_ 2332426101 BAT_SOC_HVS_53 "真实SOC";
CM_ SG_ 2332426101 BAT_User_SOC_HVS_53 "显示SOC";
CM_ SG_ 2332426101 BAT_Cell_Max_SOC_HVS_53 "单柜最大SOC";
CM_ SG_ 2332426101 BAT_Cell_Min_SOC_HVS_53 "单柜最小SOC";
CM_ SG_ 2332426101 BAT_Cool_CellBalStat_53 "冷调均衡模式状态反馈";
CM_ SG_ 2332426101 BAT_CorrectState_Require "Rack静置维护模式请求";
CM_ SG_ 2332426102 CRC_S2A_S5_54 "S2A概要数据5 的CRC";
CM_ SG_ 2332426102 BAT_SOH_HVS_54 "显示SOH";
CM_ SG_ 2332426102 BAT_SOC_HVS_54 "真实SOC";
CM_ SG_ 2332426102 BAT_User_SOC_HVS_54 "显示SOC";
CM_ SG_ 2332426102 BAT_Cell_Max_SOC_HVS_54 "单柜最大SOC";
CM_ SG_ 2332426102 BAT_Cell_Min_SOC_HVS_54 "单柜最小SOC";
CM_ SG_ 2332426102 BAT_Cool_CellBalStat_54 "冷调均衡模式状态反馈";
CM_ SG_ 2332426102 BAT_CorrectState_Require "Rack静置维护模式请求";
CM_ SG_ 2332426103 CRC_S2A_S5_55 "S2A概要数据5 的CRC";
CM_ SG_ 2332426103 BAT_SOH_HVS_55 "显示SOH";
CM_ SG_ 2332426103 BAT_SOC_HVS_55 "真实SOC";
CM_ SG_ 2332426103 BAT_User_SOC_HVS_55 "显示SOC";
CM_ SG_ 2332426103 BAT_Cell_Max_SOC_HVS_55 "单柜最大SOC";
CM_ SG_ 2332426103 BAT_Cell_Min_SOC_HVS_55 "单柜最小SOC";
CM_ SG_ 2332426103 BAT_Cool_CellBalStat_55 "冷调均衡模式状态反馈";
CM_ SG_ 2332426103 BAT_CorrectState_Require "Rack静置维护模式请求";
CM_ SG_ 2332426104 CRC_S2A_S5_56 "S2A概要数据5 的CRC";
CM_ SG_ 2332426104 BAT_SOH_HVS_56 "显示SOH";
CM_ SG_ 2332426104 BAT_SOC_HVS_56 "真实SOC";
CM_ SG_ 2332426104 BAT_User_SOC_HVS_56 "显示SOC";
CM_ SG_ 2332426104 BAT_Cell_Max_SOC_HVS_56 "单柜最大SOC";
CM_ SG_ 2332426104 BAT_Cell_Min_SOC_HVS_56 "单柜最小SOC";
CM_ SG_ 2332426104 BAT_Cool_CellBalStat_56 "冷调均衡模式状态反馈";
CM_ SG_ 2332426104 BAT_CorrectState_Require "Rack静置维护模式请求";
CM_ SG_ 2332426105 CRC_S2A_S5_57 "S2A概要数据5 的CRC";
CM_ SG_ 2332426105 BAT_SOH_HVS_57 "显示SOH";
CM_ SG_ 2332426105 BAT_SOC_HVS_57 "真实SOC";
CM_ SG_ 2332426105 BAT_User_SOC_HVS_57 "显示SOC";
CM_ SG_ 2332426105 BAT_Cell_Max_SOC_HVS_57 "单柜最大SOC";
CM_ SG_ 2332426105 BAT_Cell_Min_SOC_HVS_57 "单柜最小SOC";
CM_ SG_ 2332426105 BAT_Cool_CellBalStat_57 "冷调均衡模式状态反馈";
CM_ SG_ 2332426105 BAT_CorrectState_Require "Rack静置维护模式请求";
CM_ SG_ 2332426106 CRC_S2A_S5_58 "S2A概要数据5 的CRC";
CM_ SG_ 2332426106 BAT_SOH_HVS_58 "显示SOH";
CM_ SG_ 2332426106 BAT_SOC_HVS_58 "真实SOC";
CM_ SG_ 2332426106 BAT_User_SOC_HVS_58 "显示SOC";
CM_ SG_ 2332426106 BAT_Cell_Max_SOC_HVS_58 "单柜最大SOC";
CM_ SG_ 2332426106 BAT_Cell_Min_SOC_HVS_58 "单柜最小SOC";
CM_ SG_ 2332426106 BAT_Cool_CellBalStat_58 "冷调均衡模式状态反馈";
CM_ SG_ 2332426106 BAT_CorrectState_Require "Rack静置维护模式请求";
CM_ SG_ 2332426107 CRC_S2A_S5_59 "S2A概要数据5 的CRC";
CM_ SG_ 2332426107 BAT_SOH_HVS_59 "显示SOH";
CM_ SG_ 2332426107 BAT_SOC_HVS_59 "真实SOC";
CM_ SG_ 2332426107 BAT_User_SOC_HVS_59 "显示SOC";
CM_ SG_ 2332426107 BAT_Cell_Max_SOC_HVS_59 "单柜最大SOC";
CM_ SG_ 2332426107 BAT_Cell_Min_SOC_HVS_59 "单柜最小SOC";
CM_ SG_ 2332426107 BAT_Cool_CellBalStat_59 "冷调均衡模式状态反馈";
CM_ SG_ 2332426107 BAT_CorrectState_Require "Rack静置维护模式请求";
CM_ SG_ 2332426108 CRC_S2A_S5_60 "S2A概要数据5 的CRC";
CM_ SG_ 2332426108 BAT_SOH_HVS_60 "显示SOH";
CM_ SG_ 2332426108 BAT_SOC_HVS_60 "真实SOC";
CM_ SG_ 2332426108 BAT_User_SOC_HVS_60 "显示SOC";
CM_ SG_ 2332426108 BAT_Cell_Max_SOC_HVS_60 "单柜最大SOC";
CM_ SG_ 2332426108 BAT_Cell_Min_SOC_HVS_60 "单柜最小SOC";
CM_ SG_ 2332426108 BAT_Cool_CellBalStat_60 "冷调均衡模式状态反馈";
CM_ SG_ 2332426108 BAT_CorrectState_Require "Rack静置维护模式请求";
CM_ SG_ 2332426109 CRC_S2A_S5_61 "S2A概要数据5 的CRC";
CM_ SG_ 2332426109 BAT_SOH_HVS_61 "显示SOH";
CM_ SG_ 2332426109 BAT_SOC_HVS_61 "真实SOC";
CM_ SG_ 2332426109 BAT_User_SOC_HVS_61 "显示SOC";
CM_ SG_ 2332426109 BAT_Cell_Max_SOC_HVS_61 "单柜最大SOC";
CM_ SG_ 2332426109 BAT_Cell_Min_SOC_HVS_61 "单柜最小SOC";
CM_ SG_ 2332426109 BAT_Cool_CellBalStat_61 "冷调均衡模式状态反馈";
CM_ SG_ 2332426109 BAT_CorrectState_Require "Rack静置维护模式请求";
CM_ SG_ 2332426110 CRC_S2A_S5_62 "S2A概要数据5 的CRC";
CM_ SG_ 2332426110 BAT_SOH_HVS_62 "显示SOH";
CM_ SG_ 2332426110 BAT_SOC_HVS_62 "真实SOC";
CM_ SG_ 2332426110 BAT_User_SOC_HVS_62 "显示SOC";
CM_ SG_ 2332426110 BAT_Cell_Max_SOC_HVS_62 "单柜最大SOC";
CM_ SG_ 2332426110 BAT_Cell_Min_SOC_HVS_62 "单柜最小SOC";
CM_ SG_ 2332426110 BAT_Cool_CellBalStat_62 "冷调均衡模式状态反馈";
CM_ SG_ 2332426110 BAT_CorrectState_Require "Rack静置维护模式请求";
CM_ SG_ 2332426111 CRC_S2A_S5_63 "S2A概要数据5 的CRC";
CM_ SG_ 2332426111 BAT_SOH_HVS_63 "显示SOH";
CM_ SG_ 2332426111 BAT_SOC_HVS_63 "真实SOC";
CM_ SG_ 2332426111 BAT_User_SOC_HVS_63 "显示SOC";
CM_ SG_ 2332426111 BAT_Cell_Max_SOC_HVS_63 "单柜最大SOC";
CM_ SG_ 2332426111 BAT_Cell_Min_SOC_HVS_63 "单柜最小SOC";
CM_ SG_ 2332426111 BAT_Cool_CellBalStat_63 "冷调均衡模式状态反馈";
CM_ SG_ 2332426111 BAT_CorrectState_Require "Rack静置维护模式请求";
CM_ SG_ 2332491585 CRC_S2A_S6_01 "S2A概要数据6 的CRC";
CM_ SG_ 2332491585 SBMU_Evn_T1_01 "SBMU环境温度1";
CM_ SG_ 2332491585 SBMU_Evn_T2_01 "SBMU环境温度2";
CM_ SG_ 2332491585 SBMU_Evn_T3_01 "SBMU环境温度3";
CM_ SG_ 2332491585 S2A_STofCSCAutoCoding_01 "CSC地址自动编码状态";
CM_ SG_ 2332491586 CRC_S2A_S6_02 "S2A概要数据6 的CRC";
CM_ SG_ 2332491586 SBMU_Evn_T1_02 "SBMU环境温度1";
CM_ SG_ 2332491586 SBMU_Evn_T2_02 "SBMU环境温度2";
CM_ SG_ 2332491586 SBMU_Evn_T3_02 "SBMU环境温度3";
CM_ SG_ 2332491586 S2A_STofCSCAutoCoding_02 "CSC地址自动编码状态";
CM_ SG_ 2332491587 CRC_S2A_S6_03 "S2A概要数据6 的CRC";
CM_ SG_ 2332491587 SBMU_Evn_T1_03 "SBMU环境温度1";
CM_ SG_ 2332491587 SBMU_Evn_T2_03 "SBMU环境温度2";
CM_ SG_ 2332491587 SBMU_Evn_T3_03 "SBMU环境温度3";
CM_ SG_ 2332491587 S2A_STofCSCAutoCoding_03 "CSC地址自动编码状态";
CM_ SG_ 2332491588 CRC_S2A_S6_04 "S2A概要数据6 的CRC";
CM_ SG_ 2332491588 SBMU_Evn_T1_04 "SBMU环境温度1";
CM_ SG_ 2332491588 SBMU_Evn_T2_04 "SBMU环境温度2";
CM_ SG_ 2332491588 SBMU_Evn_T3_04 "SBMU环境温度3";
CM_ SG_ 2332491588 S2A_STofCSCAutoCoding_04 "CSC地址自动编码状态";
CM_ SG_ 2332491589 CRC_S2A_S6_05 "S2A概要数据6 的CRC";
CM_ SG_ 2332491589 SBMU_Evn_T1_05 "SBMU环境温度1";
CM_ SG_ 2332491589 SBMU_Evn_T2_05 "SBMU环境温度2";
CM_ SG_ 2332491589 SBMU_Evn_T3_05 "SBMU环境温度3";
CM_ SG_ 2332491589 S2A_STofCSCAutoCoding_05 "CSC地址自动编码状态";
CM_ SG_ 2332491590 CRC_S2A_S6_06 "S2A概要数据6 的CRC";
CM_ SG_ 2332491590 SBMU_Evn_T1_06 "SBMU环境温度1";
CM_ SG_ 2332491590 SBMU_Evn_T2_06 "SBMU环境温度2";
CM_ SG_ 2332491590 SBMU_Evn_T3_06 "SBMU环境温度3";
CM_ SG_ 2332491590 S2A_STofCSCAutoCoding_06 "CSC地址自动编码状态";
CM_ SG_ 2332491591 CRC_S2A_S6_07 "S2A概要数据6 的CRC";
CM_ SG_ 2332491591 SBMU_Evn_T1_07 "SBMU环境温度1";
CM_ SG_ 2332491591 SBMU_Evn_T2_07 "SBMU环境温度2";
CM_ SG_ 2332491591 SBMU_Evn_T3_07 "SBMU环境温度3";
CM_ SG_ 2332491591 S2A_STofCSCAutoCoding_07 "CSC地址自动编码状态";
CM_ SG_ 2332491592 CRC_S2A_S6_08 "S2A概要数据6 的CRC";
CM_ SG_ 2332491592 SBMU_Evn_T1_08 "SBMU环境温度1";
CM_ SG_ 2332491592 SBMU_Evn_T2_08 "SBMU环境温度2";
CM_ SG_ 2332491592 SBMU_Evn_T3_08 "SBMU环境温度3";
CM_ SG_ 2332491592 S2A_STofCSCAutoCoding_08 "CSC地址自动编码状态";
CM_ SG_ 2332491593 CRC_S2A_S6_09 "S2A概要数据6 的CRC";
CM_ SG_ 2332491593 SBMU_Evn_T1_09 "SBMU环境温度1";
CM_ SG_ 2332491593 SBMU_Evn_T2_09 "SBMU环境温度2";
CM_ SG_ 2332491593 SBMU_Evn_T3_09 "SBMU环境温度3";
CM_ SG_ 2332491593 S2A_STofCSCAutoCoding_09 "CSC地址自动编码状态";
CM_ SG_ 2332491594 CRC_S2A_S6_10 "S2A概要数据6 的CRC";
CM_ SG_ 2332491594 SBMU_Evn_T1_10 "SBMU环境温度1";
CM_ SG_ 2332491594 SBMU_Evn_T2_10 "SBMU环境温度2";
CM_ SG_ 2332491594 SBMU_Evn_T3_10 "SBMU环境温度3";
CM_ SG_ 2332491594 S2A_STofCSCAutoCoding_10 "CSC地址自动编码状态";
CM_ SG_ 2332491595 CRC_S2A_S6_11 "S2A概要数据6 的CRC";
CM_ SG_ 2332491595 SBMU_Evn_T1_11 "SBMU环境温度1";
CM_ SG_ 2332491595 SBMU_Evn_T2_11 "SBMU环境温度2";
CM_ SG_ 2332491595 SBMU_Evn_T3_11 "SBMU环境温度3";
CM_ SG_ 2332491595 S2A_STofCSCAutoCoding_11 "CSC地址自动编码状态";
CM_ SG_ 2332491596 CRC_S2A_S6_12 "S2A概要数据6 的CRC";
CM_ SG_ 2332491596 SBMU_Evn_T1_12 "SBMU环境温度1";
CM_ SG_ 2332491596 SBMU_Evn_T2_12 "SBMU环境温度2";
CM_ SG_ 2332491596 SBMU_Evn_T3_12 "SBMU环境温度3";
CM_ SG_ 2332491596 S2A_STofCSCAutoCoding_12 "CSC地址自动编码状态";
CM_ SG_ 2332491597 CRC_S2A_S6_13 "S2A概要数据6 的CRC";
CM_ SG_ 2332491597 SBMU_Evn_T1_13 "SBMU环境温度1";
CM_ SG_ 2332491597 SBMU_Evn_T2_13 "SBMU环境温度2";
CM_ SG_ 2332491597 SBMU_Evn_T3_13 "SBMU环境温度3";
CM_ SG_ 2332491597 S2A_STofCSCAutoCoding_13 "CSC地址自动编码状态";
CM_ SG_ 2332491598 CRC_S2A_S6_14 "S2A概要数据6 的CRC";
CM_ SG_ 2332491598 SBMU_Evn_T1_14 "SBMU环境温度1";
CM_ SG_ 2332491598 SBMU_Evn_T2_14 "SBMU环境温度2";
CM_ SG_ 2332491598 SBMU_Evn_T3_14 "SBMU环境温度3";
CM_ SG_ 2332491598 S2A_STofCSCAutoCoding_14 "CSC地址自动编码状态";
CM_ SG_ 2332491599 CRC_S2A_S6_15 "S2A概要数据6 的CRC";
CM_ SG_ 2332491599 SBMU_Evn_T1_15 "SBMU环境温度1";
CM_ SG_ 2332491599 SBMU_Evn_T2_15 "SBMU环境温度2";
CM_ SG_ 2332491599 SBMU_Evn_T3_15 "SBMU环境温度3";
CM_ SG_ 2332491599 S2A_STofCSCAutoCoding_15 "CSC地址自动编码状态";
CM_ SG_ 2332491600 CRC_S2A_S6_16 "S2A概要数据6 的CRC";
CM_ SG_ 2332491600 SBMU_Evn_T1_16 "SBMU环境温度1";
CM_ SG_ 2332491600 SBMU_Evn_T2_16 "SBMU环境温度2";
CM_ SG_ 2332491600 SBMU_Evn_T3_16 "SBMU环境温度3";
CM_ SG_ 2332491600 S2A_STofCSCAutoCoding_16 "CSC地址自动编码状态";
CM_ SG_ 2332491601 CRC_S2A_S6_17 "S2A概要数据6 的CRC";
CM_ SG_ 2332491601 SBMU_Evn_T1_17 "SBMU环境温度1";
CM_ SG_ 2332491601 SBMU_Evn_T2_17 "SBMU环境温度2";
CM_ SG_ 2332491601 SBMU_Evn_T3_17 "SBMU环境温度3";
CM_ SG_ 2332491601 S2A_STofCSCAutoCoding_17 "CSC地址自动编码状态";
CM_ SG_ 2332491602 CRC_S2A_S6_18 "S2A概要数据6 的CRC";
CM_ SG_ 2332491602 SBMU_Evn_T1_18 "SBMU环境温度1";
CM_ SG_ 2332491602 SBMU_Evn_T2_18 "SBMU环境温度2";
CM_ SG_ 2332491602 SBMU_Evn_T3_18 "SBMU环境温度3";
CM_ SG_ 2332491602 S2A_STofCSCAutoCoding_18 "CSC地址自动编码状态";
CM_ SG_ 2332491603 CRC_S2A_S6_19 "S2A概要数据6 的CRC";
CM_ SG_ 2332491603 SBMU_Evn_T1_19 "SBMU环境温度1";
CM_ SG_ 2332491603 SBMU_Evn_T2_19 "SBMU环境温度2";
CM_ SG_ 2332491603 SBMU_Evn_T3_19 "SBMU环境温度3";
CM_ SG_ 2332491603 S2A_STofCSCAutoCoding_19 "CSC地址自动编码状态";
CM_ SG_ 2332491604 CRC_S2A_S6_20 "S2A概要数据6 的CRC";
CM_ SG_ 2332491604 SBMU_Evn_T1_20 "SBMU环境温度1";
CM_ SG_ 2332491604 SBMU_Evn_T2_20 "SBMU环境温度2";
CM_ SG_ 2332491604 SBMU_Evn_T3_20 "SBMU环境温度3";
CM_ SG_ 2332491604 S2A_STofCSCAutoCoding_20 "CSC地址自动编码状态";
CM_ SG_ 2332491605 CRC_S2A_S6_21 "S2A概要数据6 的CRC";
CM_ SG_ 2332491605 SBMU_Evn_T1_21 "SBMU环境温度1";
CM_ SG_ 2332491605 SBMU_Evn_T2_21 "SBMU环境温度2";
CM_ SG_ 2332491605 SBMU_Evn_T3_21 "SBMU环境温度3";
CM_ SG_ 2332491605 S2A_STofCSCAutoCoding_21 "CSC地址自动编码状态";
CM_ SG_ 2332491606 CRC_S2A_S6_22 "S2A概要数据6 的CRC";
CM_ SG_ 2332491606 SBMU_Evn_T1_22 "SBMU环境温度1";
CM_ SG_ 2332491606 SBMU_Evn_T2_22 "SBMU环境温度2";
CM_ SG_ 2332491606 SBMU_Evn_T3_22 "SBMU环境温度3";
CM_ SG_ 2332491606 S2A_STofCSCAutoCoding_22 "CSC地址自动编码状态";
CM_ SG_ 2332491607 CRC_S2A_S6_23 "S2A概要数据6 的CRC";
CM_ SG_ 2332491607 SBMU_Evn_T1_23 "SBMU环境温度1";
CM_ SG_ 2332491607 SBMU_Evn_T2_23 "SBMU环境温度2";
CM_ SG_ 2332491607 SBMU_Evn_T3_23 "SBMU环境温度3";
CM_ SG_ 2332491607 S2A_STofCSCAutoCoding_23 "CSC地址自动编码状态";
CM_ SG_ 2332491608 CRC_S2A_S6_24 "S2A概要数据6 的CRC";
CM_ SG_ 2332491608 SBMU_Evn_T1_24 "SBMU环境温度1";
CM_ SG_ 2332491608 SBMU_Evn_T2_24 "SBMU环境温度2";
CM_ SG_ 2332491608 SBMU_Evn_T3_24 "SBMU环境温度3";
CM_ SG_ 2332491608 S2A_STofCSCAutoCoding_24 "CSC地址自动编码状态";
CM_ SG_ 2332491609 CRC_S2A_S6_25 "S2A概要数据6 的CRC";
CM_ SG_ 2332491609 SBMU_Evn_T1_25 "SBMU环境温度1";
CM_ SG_ 2332491609 SBMU_Evn_T2_25 "SBMU环境温度2";
CM_ SG_ 2332491609 SBMU_Evn_T3_25 "SBMU环境温度3";
CM_ SG_ 2332491609 S2A_STofCSCAutoCoding_25 "CSC地址自动编码状态";
CM_ SG_ 2332491610 CRC_S2A_S6_26 "S2A概要数据6 的CRC";
CM_ SG_ 2332491610 SBMU_Evn_T1_26 "SBMU环境温度1";
CM_ SG_ 2332491610 SBMU_Evn_T2_26 "SBMU环境温度2";
CM_ SG_ 2332491610 SBMU_Evn_T3_26 "SBMU环境温度3";
CM_ SG_ 2332491610 S2A_STofCSCAutoCoding_26 "CSC地址自动编码状态";
CM_ SG_ 2332491611 CRC_S2A_S6_27 "S2A概要数据6 的CRC";
CM_ SG_ 2332491611 SBMU_Evn_T1_27 "SBMU环境温度1";
CM_ SG_ 2332491611 SBMU_Evn_T2_27 "SBMU环境温度2";
CM_ SG_ 2332491611 SBMU_Evn_T3_27 "SBMU环境温度3";
CM_ SG_ 2332491611 S2A_STofCSCAutoCoding_27 "CSC地址自动编码状态";
CM_ SG_ 2332491612 CRC_S2A_S6_28 "S2A概要数据6 的CRC";
CM_ SG_ 2332491612 SBMU_Evn_T1_28 "SBMU环境温度1";
CM_ SG_ 2332491612 SBMU_Evn_T2_28 "SBMU环境温度2";
CM_ SG_ 2332491612 SBMU_Evn_T3_28 "SBMU环境温度3";
CM_ SG_ 2332491612 S2A_STofCSCAutoCoding_28 "CSC地址自动编码状态";
CM_ SG_ 2332491613 CRC_S2A_S6_29 "S2A概要数据6 的CRC";
CM_ SG_ 2332491613 SBMU_Evn_T1_29 "SBMU环境温度1";
CM_ SG_ 2332491613 SBMU_Evn_T2_29 "SBMU环境温度2";
CM_ SG_ 2332491613 SBMU_Evn_T3_29 "SBMU环境温度3";
CM_ SG_ 2332491613 S2A_STofCSCAutoCoding_29 "CSC地址自动编码状态";
CM_ SG_ 2332491614 CRC_S2A_S6_30 "S2A概要数据6 的CRC";
CM_ SG_ 2332491614 SBMU_Evn_T1_30 "SBMU环境温度1";
CM_ SG_ 2332491614 SBMU_Evn_T2_30 "SBMU环境温度2";
CM_ SG_ 2332491614 SBMU_Evn_T3_30 "SBMU环境温度3";
CM_ SG_ 2332491614 S2A_STofCSCAutoCoding_30 "CSC地址自动编码状态";
CM_ SG_ 2332491615 CRC_S2A_S6_31 "S2A概要数据6 的CRC";
CM_ SG_ 2332491615 SBMU_Evn_T1_31 "SBMU环境温度1";
CM_ SG_ 2332491615 SBMU_Evn_T2_31 "SBMU环境温度2";
CM_ SG_ 2332491615 SBMU_Evn_T3_31 "SBMU环境温度3";
CM_ SG_ 2332491615 S2A_STofCSCAutoCoding_31 "CSC地址自动编码状态";
CM_ SG_ 2332491616 CRC_S2A_S6_32 "S2A概要数据6 的CRC";
CM_ SG_ 2332491616 SBMU_Evn_T1_32 "SBMU环境温度1";
CM_ SG_ 2332491616 SBMU_Evn_T2_32 "SBMU环境温度2";
CM_ SG_ 2332491616 SBMU_Evn_T3_32 "SBMU环境温度3";
CM_ SG_ 2332491616 S2A_STofCSCAutoCoding_32 "CSC地址自动编码状态";
CM_ SG_ 2332491617 CRC_S2A_S6_33 "S2A概要数据6 的CRC";
CM_ SG_ 2332491617 SBMU_Evn_T1_33 "SBMU环境温度1";
CM_ SG_ 2332491617 SBMU_Evn_T2_33 "SBMU环境温度2";
CM_ SG_ 2332491617 SBMU_Evn_T3_33 "SBMU环境温度3";
CM_ SG_ 2332491617 S2A_STofCSCAutoCoding_33 "CSC地址自动编码状态";
CM_ SG_ 2332491618 CRC_S2A_S6_34 "S2A概要数据6 的CRC";
CM_ SG_ 2332491618 SBMU_Evn_T1_34 "SBMU环境温度1";
CM_ SG_ 2332491618 SBMU_Evn_T2_34 "SBMU环境温度2";
CM_ SG_ 2332491618 SBMU_Evn_T3_34 "SBMU环境温度3";
CM_ SG_ 2332491618 S2A_STofCSCAutoCoding_34 "CSC地址自动编码状态";
CM_ SG_ 2332491619 CRC_S2A_S6_35 "S2A概要数据6 的CRC";
CM_ SG_ 2332491619 SBMU_Evn_T1_35 "SBMU环境温度1";
CM_ SG_ 2332491619 SBMU_Evn_T2_35 "SBMU环境温度2";
CM_ SG_ 2332491619 SBMU_Evn_T3_35 "SBMU环境温度3";
CM_ SG_ 2332491619 S2A_STofCSCAutoCoding_35 "CSC地址自动编码状态";
CM_ SG_ 2332491620 CRC_S2A_S6_36 "S2A概要数据6 的CRC";
CM_ SG_ 2332491620 SBMU_Evn_T1_36 "SBMU环境温度1";
CM_ SG_ 2332491620 SBMU_Evn_T2_36 "SBMU环境温度2";
CM_ SG_ 2332491620 SBMU_Evn_T3_36 "SBMU环境温度3";
CM_ SG_ 2332491620 S2A_STofCSCAutoCoding_36 "CSC地址自动编码状态";
CM_ SG_ 2332491621 CRC_S2A_S6_37 "S2A概要数据6 的CRC";
CM_ SG_ 2332491621 SBMU_Evn_T1_37 "SBMU环境温度1";
CM_ SG_ 2332491621 SBMU_Evn_T2_37 "SBMU环境温度2";
CM_ SG_ 2332491621 SBMU_Evn_T3_37 "SBMU环境温度3";
CM_ SG_ 2332491621 S2A_STofCSCAutoCoding_37 "CSC地址自动编码状态";
CM_ SG_ 2332491622 CRC_S2A_S6_38 "S2A概要数据6 的CRC";
CM_ SG_ 2332491622 SBMU_Evn_T1_38 "SBMU环境温度1";
CM_ SG_ 2332491622 SBMU_Evn_T2_38 "SBMU环境温度2";
CM_ SG_ 2332491622 SBMU_Evn_T3_38 "SBMU环境温度3";
CM_ SG_ 2332491622 S2A_STofCSCAutoCoding_38 "CSC地址自动编码状态";
CM_ SG_ 2332491623 CRC_S2A_S6_39 "S2A概要数据6 的CRC";
CM_ SG_ 2332491623 SBMU_Evn_T1_39 "SBMU环境温度1";
CM_ SG_ 2332491623 SBMU_Evn_T2_39 "SBMU环境温度2";
CM_ SG_ 2332491623 SBMU_Evn_T3_39 "SBMU环境温度3";
CM_ SG_ 2332491623 S2A_STofCSCAutoCoding_39 "CSC地址自动编码状态";
CM_ SG_ 2332491624 CRC_S2A_S6_40 "S2A概要数据6 的CRC";
CM_ SG_ 2332491624 SBMU_Evn_T1_40 "SBMU环境温度1";
CM_ SG_ 2332491624 SBMU_Evn_T2_40 "SBMU环境温度2";
CM_ SG_ 2332491624 SBMU_Evn_T3_40 "SBMU环境温度3";
CM_ SG_ 2332491624 S2A_STofCSCAutoCoding_40 "CSC地址自动编码状态";
CM_ SG_ 2332491625 CRC_S2A_S6_41 "S2A概要数据6 的CRC";
CM_ SG_ 2332491625 SBMU_Evn_T1_41 "SBMU环境温度1";
CM_ SG_ 2332491625 SBMU_Evn_T2_41 "SBMU环境温度2";
CM_ SG_ 2332491625 SBMU_Evn_T3_41 "SBMU环境温度3";
CM_ SG_ 2332491625 S2A_STofCSCAutoCoding_41 "CSC地址自动编码状态";
CM_ SG_ 2332491626 CRC_S2A_S6_42 "S2A概要数据6 的CRC";
CM_ SG_ 2332491626 SBMU_Evn_T1_42 "SBMU环境温度1";
CM_ SG_ 2332491626 SBMU_Evn_T2_42 "SBMU环境温度2";
CM_ SG_ 2332491626 SBMU_Evn_T3_42 "SBMU环境温度3";
CM_ SG_ 2332491626 S2A_STofCSCAutoCoding_42 "CSC地址自动编码状态";
CM_ SG_ 2332491627 CRC_S2A_S6_43 "S2A概要数据6 的CRC";
CM_ SG_ 2332491627 SBMU_Evn_T1_43 "SBMU环境温度1";
CM_ SG_ 2332491627 SBMU_Evn_T2_43 "SBMU环境温度2";
CM_ SG_ 2332491627 SBMU_Evn_T3_43 "SBMU环境温度3";
CM_ SG_ 2332491627 S2A_STofCSCAutoCoding_43 "CSC地址自动编码状态";
CM_ SG_ 2332491628 CRC_S2A_S6_44 "S2A概要数据6 的CRC";
CM_ SG_ 2332491628 SBMU_Evn_T1_44 "SBMU环境温度1";
CM_ SG_ 2332491628 SBMU_Evn_T2_44 "SBMU环境温度2";
CM_ SG_ 2332491628 SBMU_Evn_T3_44 "SBMU环境温度3";
CM_ SG_ 2332491628 S2A_STofCSCAutoCoding_44 "CSC地址自动编码状态";
CM_ SG_ 2332491629 CRC_S2A_S6_45 "S2A概要数据6 的CRC";
CM_ SG_ 2332491629 SBMU_Evn_T1_45 "SBMU环境温度1";
CM_ SG_ 2332491629 SBMU_Evn_T2_45 "SBMU环境温度2";
CM_ SG_ 2332491629 SBMU_Evn_T3_45 "SBMU环境温度3";
CM_ SG_ 2332491629 S2A_STofCSCAutoCoding_45 "CSC地址自动编码状态";
CM_ SG_ 2332491630 CRC_S2A_S6_46 "S2A概要数据6 的CRC";
CM_ SG_ 2332491630 SBMU_Evn_T1_46 "SBMU环境温度1";
CM_ SG_ 2332491630 SBMU_Evn_T2_46 "SBMU环境温度2";
CM_ SG_ 2332491630 SBMU_Evn_T3_46 "SBMU环境温度3";
CM_ SG_ 2332491630 S2A_STofCSCAutoCoding_46 "CSC地址自动编码状态";
CM_ SG_ 2332491631 CRC_S2A_S6_47 "S2A概要数据6 的CRC";
CM_ SG_ 2332491631 SBMU_Evn_T1_47 "SBMU环境温度1";
CM_ SG_ 2332491631 SBMU_Evn_T2_47 "SBMU环境温度2";
CM_ SG_ 2332491631 SBMU_Evn_T3_47 "SBMU环境温度3";
CM_ SG_ 2332491631 S2A_STofCSCAutoCoding_47 "CSC地址自动编码状态";
CM_ SG_ 2332491632 CRC_S2A_S6_48 "S2A概要数据6 的CRC";
CM_ SG_ 2332491632 SBMU_Evn_T1_48 "SBMU环境温度1";
CM_ SG_ 2332491632 SBMU_Evn_T2_48 "SBMU环境温度2";
CM_ SG_ 2332491632 SBMU_Evn_T3_48 "SBMU环境温度3";
CM_ SG_ 2332491632 S2A_STofCSCAutoCoding_48 "CSC地址自动编码状态";
CM_ SG_ 2332491633 CRC_S2A_S6_49 "S2A概要数据6 的CRC";
CM_ SG_ 2332491633 SBMU_Evn_T1_49 "SBMU环境温度1";
CM_ SG_ 2332491633 SBMU_Evn_T2_49 "SBMU环境温度2";
CM_ SG_ 2332491633 SBMU_Evn_T3_49 "SBMU环境温度3";
CM_ SG_ 2332491633 S2A_STofCSCAutoCoding_49 "CSC地址自动编码状态";
CM_ SG_ 2332491634 CRC_S2A_S6_50 "S2A概要数据6 的CRC";
CM_ SG_ 2332491634 SBMU_Evn_T1_50 "SBMU环境温度1";
CM_ SG_ 2332491634 SBMU_Evn_T2_50 "SBMU环境温度2";
CM_ SG_ 2332491634 SBMU_Evn_T3_50 "SBMU环境温度3";
CM_ SG_ 2332491634 S2A_STofCSCAutoCoding_50 "CSC地址自动编码状态";
CM_ SG_ 2332491635 CRC_S2A_S6_51 "S2A概要数据6 的CRC";
CM_ SG_ 2332491635 SBMU_Evn_T1_51 "SBMU环境温度1";
CM_ SG_ 2332491635 SBMU_Evn_T2_51 "SBMU环境温度2";
CM_ SG_ 2332491635 SBMU_Evn_T3_51 "SBMU环境温度3";
CM_ SG_ 2332491635 S2A_STofCSCAutoCoding_51 "CSC地址自动编码状态";
CM_ SG_ 2332491636 CRC_S2A_S6_52 "S2A概要数据6 的CRC";
CM_ SG_ 2332491636 SBMU_Evn_T1_52 "SBMU环境温度1";
CM_ SG_ 2332491636 SBMU_Evn_T2_52 "SBMU环境温度2";
CM_ SG_ 2332491636 SBMU_Evn_T3_52 "SBMU环境温度3";
CM_ SG_ 2332491636 S2A_STofCSCAutoCoding_52 "CSC地址自动编码状态";
CM_ SG_ 2332491637 CRC_S2A_S6_53 "S2A概要数据6 的CRC";
CM_ SG_ 2332491637 SBMU_Evn_T1_53 "SBMU环境温度1";
CM_ SG_ 2332491637 SBMU_Evn_T2_53 "SBMU环境温度2";
CM_ SG_ 2332491637 SBMU_Evn_T3_53 "SBMU环境温度3";
CM_ SG_ 2332491637 S2A_STofCSCAutoCoding_53 "CSC地址自动编码状态";
CM_ SG_ 2332491638 CRC_S2A_S6_54 "S2A概要数据6 的CRC";
CM_ SG_ 2332491638 SBMU_Evn_T1_54 "SBMU环境温度1";
CM_ SG_ 2332491638 SBMU_Evn_T2_54 "SBMU环境温度2";
CM_ SG_ 2332491638 SBMU_Evn_T3_54 "SBMU环境温度3";
CM_ SG_ 2332491638 S2A_STofCSCAutoCoding_54 "CSC地址自动编码状态";
CM_ SG_ 2332491639 CRC_S2A_S6_55 "S2A概要数据6 的CRC";
CM_ SG_ 2332491639 SBMU_Evn_T1_55 "SBMU环境温度1";
CM_ SG_ 2332491639 SBMU_Evn_T2_55 "SBMU环境温度2";
CM_ SG_ 2332491639 SBMU_Evn_T3_55 "SBMU环境温度3";
CM_ SG_ 2332491639 S2A_STofCSCAutoCoding_55 "CSC地址自动编码状态";
CM_ SG_ 2332491640 CRC_S2A_S6_56 "S2A概要数据6 的CRC";
CM_ SG_ 2332491640 SBMU_Evn_T1_56 "SBMU环境温度1";
CM_ SG_ 2332491640 SBMU_Evn_T2_56 "SBMU环境温度2";
CM_ SG_ 2332491640 SBMU_Evn_T3_56 "SBMU环境温度3";
CM_ SG_ 2332491640 S2A_STofCSCAutoCoding_56 "CSC地址自动编码状态";
CM_ SG_ 2332491641 CRC_S2A_S6_57 "S2A概要数据6 的CRC";
CM_ SG_ 2332491641 SBMU_Evn_T1_57 "SBMU环境温度1";
CM_ SG_ 2332491641 SBMU_Evn_T2_57 "SBMU环境温度2";
CM_ SG_ 2332491641 SBMU_Evn_T3_57 "SBMU环境温度3";
CM_ SG_ 2332491641 S2A_STofCSCAutoCoding_57 "CSC地址自动编码状态";
CM_ SG_ 2332491642 CRC_S2A_S6_58 "S2A概要数据6 的CRC";
CM_ SG_ 2332491642 SBMU_Evn_T1_58 "SBMU环境温度1";
CM_ SG_ 2332491642 SBMU_Evn_T2_58 "SBMU环境温度2";
CM_ SG_ 2332491642 SBMU_Evn_T3_58 "SBMU环境温度3";
CM_ SG_ 2332491642 S2A_STofCSCAutoCoding_58 "CSC地址自动编码状态";
CM_ SG_ 2332491643 CRC_S2A_S6_59 "S2A概要数据6 的CRC";
CM_ SG_ 2332491643 SBMU_Evn_T1_59 "SBMU环境温度1";
CM_ SG_ 2332491643 SBMU_Evn_T2_59 "SBMU环境温度2";
CM_ SG_ 2332491643 SBMU_Evn_T3_59 "SBMU环境温度3";
CM_ SG_ 2332491643 S2A_STofCSCAutoCoding_59 "CSC地址自动编码状态";
CM_ SG_ 2332491644 CRC_S2A_S6_60 "S2A概要数据6 的CRC";
CM_ SG_ 2332491644 SBMU_Evn_T1_60 "SBMU环境温度1";
CM_ SG_ 2332491644 SBMU_Evn_T2_60 "SBMU环境温度2";
CM_ SG_ 2332491644 SBMU_Evn_T3_60 "SBMU环境温度3";
CM_ SG_ 2332491644 S2A_STofCSCAutoCoding_60 "CSC地址自动编码状态";
CM_ SG_ 2332491645 CRC_S2A_S6_61 "S2A概要数据6 的CRC";
CM_ SG_ 2332491645 SBMU_Evn_T1_61 "SBMU环境温度1";
CM_ SG_ 2332491645 SBMU_Evn_T2_61 "SBMU环境温度2";
CM_ SG_ 2332491645 SBMU_Evn_T3_61 "SBMU环境温度3";
CM_ SG_ 2332491645 S2A_STofCSCAutoCoding_61 "CSC地址自动编码状态";
CM_ SG_ 2332491646 CRC_S2A_S6_62 "S2A概要数据6 的CRC";
CM_ SG_ 2332491646 SBMU_Evn_T1_62 "SBMU环境温度1";
CM_ SG_ 2332491646 SBMU_Evn_T2_62 "SBMU环境温度2";
CM_ SG_ 2332491646 SBMU_Evn_T3_62 "SBMU环境温度3";
CM_ SG_ 2332491646 S2A_STofCSCAutoCoding_62 "CSC地址自动编码状态";
CM_ SG_ 2332491647 CRC_S2A_S6_63 "S2A概要数据6 的CRC";
CM_ SG_ 2332491647 SBMU_Evn_T1_63 "SBMU环境温度1";
CM_ SG_ 2332491647 SBMU_Evn_T2_63 "SBMU环境温度2";
CM_ SG_ 2332491647 SBMU_Evn_T3_63 "SBMU环境温度3";
CM_ SG_ 2332491647 S2A_STofCSCAutoCoding_63 "CSC地址自动编码状态";
CM_ SG_ 2332557121 CRC_S2A_S7_01 "S2A概要数据7 的CRC";
CM_ SG_ 2332557121 BAT_SOC_CorrectState_01 "SOC修正状态（最后一次）";
CM_ SG_ 2332557121 Status_of_Closed_Loop "闭环算法开启状态";
CM_ SG_ 2332557121 S2A_S7_FullDisChgFlgFromSBMU_01 "满放标志位";
CM_ SG_ 2332557121 S2A_S7_MaxSelfDischgRates_01 "电池簇电芯月自放电率最大值";
CM_ SG_ 2332557121 S2A_S7_MinSelfDischgRates_01 "电池簇电芯月自放电率最小值";
CM_ SG_ 2332557121 S2A_S7_AvgSelfDischgRates_01 "电池簇电芯月自放电率平均值";
CM_ SG_ 2332557121 S2A_S7_SOH_01 "平均SOH ";
CM_ SG_ 2332557122 CRC_S2A_S7_02 "S2A概要数据7 的CRC";
CM_ SG_ 2332557122 BAT_SOC_CorrectState_02 "SOC修正状态（最后一次）";
CM_ SG_ 2332557122 Status_of_Closed_Loop "闭环算法开启状态";
CM_ SG_ 2332557122 S2A_S7_FullDisChgFlgFromSBMU_02 "满放标志位";
CM_ SG_ 2332557122 S2A_S7_MaxSelfDischgRates_02 "电池簇电芯月自放电率最大值";
CM_ SG_ 2332557122 S2A_S7_MinSelfDischgRates_02 "电池簇电芯月自放电率最小值";
CM_ SG_ 2332557122 S2A_S7_AvgSelfDischgRates_02 "电池簇电芯月自放电率平均值";
CM_ SG_ 2332557122 S2A_S7_SOH_02 "平均SOH ";
CM_ SG_ 2332557123 CRC_S2A_S7_03 "S2A概要数据7 的CRC";
CM_ SG_ 2332557123 BAT_SOC_CorrectState_03 "SOC修正状态（最后一次）";
CM_ SG_ 2332557123 Status_of_Closed_Loop "闭环算法开启状态";
CM_ SG_ 2332557123 S2A_S7_FullDisChgFlgFromSBMU_03 "满放标志位";
CM_ SG_ 2332557123 S2A_S7_MaxSelfDischgRates_03 "电池簇电芯月自放电率最大值";
CM_ SG_ 2332557123 S2A_S7_MinSelfDischgRates_03 "电池簇电芯月自放电率最小值";
CM_ SG_ 2332557123 S2A_S7_AvgSelfDischgRates_03 "电池簇电芯月自放电率平均值";
CM_ SG_ 2332557123 S2A_S7_SOH_03 "平均SOH ";
CM_ SG_ 2332557124 CRC_S2A_S7_04 "S2A概要数据7 的CRC";
CM_ SG_ 2332557124 BAT_SOC_CorrectState_04 "SOC修正状态（最后一次）";
CM_ SG_ 2332557124 Status_of_Closed_Loop "闭环算法开启状态";
CM_ SG_ 2332557124 S2A_S7_FullDisChgFlgFromSBMU_04 "满放标志位";
CM_ SG_ 2332557124 S2A_S7_MaxSelfDischgRates_04 "电池簇电芯月自放电率最大值";
CM_ SG_ 2332557124 S2A_S7_MinSelfDischgRates_04 "电池簇电芯月自放电率最小值";
CM_ SG_ 2332557124 S2A_S7_AvgSelfDischgRates_04 "电池簇电芯月自放电率平均值";
CM_ SG_ 2332557124 S2A_S7_SOH_04 "平均SOH ";
CM_ SG_ 2332557125 CRC_S2A_S7_05 "S2A概要数据7 的CRC";
CM_ SG_ 2332557125 BAT_SOC_CorrectState_05 "SOC修正状态（最后一次）";
CM_ SG_ 2332557125 Status_of_Closed_Loop "闭环算法开启状态";
CM_ SG_ 2332557125 S2A_S7_FullDisChgFlgFromSBMU_05 "满放标志位";
CM_ SG_ 2332557125 S2A_S7_MaxSelfDischgRates_05 "电池簇电芯月自放电率最大值";
CM_ SG_ 2332557125 S2A_S7_MinSelfDischgRates_05 "电池簇电芯月自放电率最小值";
CM_ SG_ 2332557125 S2A_S7_AvgSelfDischgRates_05 "电池簇电芯月自放电率平均值";
CM_ SG_ 2332557125 S2A_S7_SOH_05 "平均SOH ";
CM_ SG_ 2332557126 CRC_S2A_S7_06 "S2A概要数据7 的CRC";
CM_ SG_ 2332557126 BAT_SOC_CorrectState_06 "SOC修正状态（最后一次）";
CM_ SG_ 2332557126 Status_of_Closed_Loop "闭环算法开启状态";
CM_ SG_ 2332557126 S2A_S7_FullDisChgFlgFromSBMU_06 "满放标志位";
CM_ SG_ 2332557126 S2A_S7_MaxSelfDischgRates_06 "电池簇电芯月自放电率最大值";
CM_ SG_ 2332557126 S2A_S7_MinSelfDischgRates_06 "电池簇电芯月自放电率最小值";
CM_ SG_ 2332557126 S2A_S7_AvgSelfDischgRates_06 "电池簇电芯月自放电率平均值";
CM_ SG_ 2332557126 S2A_S7_SOH_06 "平均SOH ";
CM_ SG_ 2332557127 CRC_S2A_S7_07 "S2A概要数据7 的CRC";
CM_ SG_ 2332557127 BAT_SOC_CorrectState_07 "SOC修正状态（最后一次）";
CM_ SG_ 2332557127 Status_of_Closed_Loop "闭环算法开启状态";
CM_ SG_ 2332557127 S2A_S7_FullDisChgFlgFromSBMU_07 "满放标志位";
CM_ SG_ 2332557127 S2A_S7_MaxSelfDischgRates_07 "电池簇电芯月自放电率最大值";
CM_ SG_ 2332557127 S2A_S7_MinSelfDischgRates_07 "电池簇电芯月自放电率最小值";
CM_ SG_ 2332557127 S2A_S7_AvgSelfDischgRates_07 "电池簇电芯月自放电率平均值";
CM_ SG_ 2332557127 S2A_S7_SOH_07 "平均SOH ";
CM_ SG_ 2332557128 CRC_S2A_S7_08 "S2A概要数据7 的CRC";
CM_ SG_ 2332557128 BAT_SOC_CorrectState_08 "SOC修正状态（最后一次）";
CM_ SG_ 2332557128 Status_of_Closed_Loop "闭环算法开启状态";
CM_ SG_ 2332557128 S2A_S7_FullDisChgFlgFromSBMU_08 "满放标志位";
CM_ SG_ 2332557128 S2A_S7_MaxSelfDischgRates_08 "电池簇电芯月自放电率最大值";
CM_ SG_ 2332557128 S2A_S7_MinSelfDischgRates_08 "电池簇电芯月自放电率最小值";
CM_ SG_ 2332557128 S2A_S7_AvgSelfDischgRates_08 "电池簇电芯月自放电率平均值";
CM_ SG_ 2332557128 S2A_S7_SOH_08 "平均SOH ";
CM_ SG_ 2332557129 CRC_S2A_S7_09 "S2A概要数据7 的CRC";
CM_ SG_ 2332557129 BAT_SOC_CorrectState_09 "SOC修正状态（最后一次）";
CM_ SG_ 2332557129 Status_of_Closed_Loop "闭环算法开启状态";
CM_ SG_ 2332557129 S2A_S7_FullDisChgFlgFromSBMU_09 "满放标志位";
CM_ SG_ 2332557129 S2A_S7_MaxSelfDischgRates_09 "电池簇电芯月自放电率最大值";
CM_ SG_ 2332557129 S2A_S7_MinSelfDischgRates_09 "电池簇电芯月自放电率最小值";
CM_ SG_ 2332557129 S2A_S7_AvgSelfDischgRates_09 "电池簇电芯月自放电率平均值";
CM_ SG_ 2332557129 S2A_S7_SOH_09 "平均SOH ";
CM_ SG_ 2332557130 CRC_S2A_S7_10 "S2A概要数据7 的CRC";
CM_ SG_ 2332557130 BAT_SOC_CorrectState_10 "SOC修正状态（最后一次）";
CM_ SG_ 2332557130 Status_of_Closed_Loop "闭环算法开启状态";
CM_ SG_ 2332557130 S2A_S7_FullDisChgFlgFromSBMU_10 "满放标志位";
CM_ SG_ 2332557130 S2A_S7_MaxSelfDischgRates_10 "电池簇电芯月自放电率最大值";
CM_ SG_ 2332557130 S2A_S7_MinSelfDischgRates_10 "电池簇电芯月自放电率最小值";
CM_ SG_ 2332557130 S2A_S7_AvgSelfDischgRates_10 "电池簇电芯月自放电率平均值";
CM_ SG_ 2332557130 S2A_S7_SOH_10 "平均SOH ";
CM_ SG_ 2332557131 CRC_S2A_S7_11 "S2A概要数据7 的CRC";
CM_ SG_ 2332557131 BAT_SOC_CorrectState_11 "SOC修正状态（最后一次）";
CM_ SG_ 2332557131 Status_of_Closed_Loop "闭环算法开启状态";
CM_ SG_ 2332557131 S2A_S7_FullDisChgFlgFromSBMU_11 "满放标志位";
CM_ SG_ 2332557131 S2A_S7_MaxSelfDischgRates_11 "电池簇电芯月自放电率最大值";
CM_ SG_ 2332557131 S2A_S7_MinSelfDischgRates_11 "电池簇电芯月自放电率最小值";
CM_ SG_ 2332557131 S2A_S7_AvgSelfDischgRates_11 "电池簇电芯月自放电率平均值";
CM_ SG_ 2332557131 S2A_S7_SOH_11 "平均SOH ";
CM_ SG_ 2332557132 CRC_S2A_S7_12 "S2A概要数据7 的CRC";
CM_ SG_ 2332557132 BAT_SOC_CorrectState_12 "SOC修正状态（最后一次）";
CM_ SG_ 2332557132 Status_of_Closed_Loop "闭环算法开启状态";
CM_ SG_ 2332557132 S2A_S7_FullDisChgFlgFromSBMU_12 "满放标志位";
CM_ SG_ 2332557132 S2A_S7_MaxSelfDischgRates_12 "电池簇电芯月自放电率最大值";
CM_ SG_ 2332557132 S2A_S7_MinSelfDischgRates_12 "电池簇电芯月自放电率最小值";
CM_ SG_ 2332557132 S2A_S7_AvgSelfDischgRates_12 "电池簇电芯月自放电率平均值";
CM_ SG_ 2332557132 S2A_S7_SOH_12 "平均SOH ";
CM_ SG_ 2332557133 CRC_S2A_S7_13 "S2A概要数据7 的CRC";
CM_ SG_ 2332557133 BAT_SOC_CorrectState_13 "SOC修正状态（最后一次）";
CM_ SG_ 2332557133 Status_of_Closed_Loop "闭环算法开启状态";
CM_ SG_ 2332557133 S2A_S7_FullDisChgFlgFromSBMU_13 "满放标志位";
CM_ SG_ 2332557133 S2A_S7_MaxSelfDischgRates_13 "电池簇电芯月自放电率最大值";
CM_ SG_ 2332557133 S2A_S7_MinSelfDischgRates_13 "电池簇电芯月自放电率最小值";
CM_ SG_ 2332557133 S2A_S7_AvgSelfDischgRates_13 "电池簇电芯月自放电率平均值";
CM_ SG_ 2332557133 S2A_S7_SOH_13 "平均SOH ";
CM_ SG_ 2332557134 CRC_S2A_S7_14 "S2A概要数据7 的CRC";
CM_ SG_ 2332557134 BAT_SOC_CorrectState_14 "SOC修正状态（最后一次）";
CM_ SG_ 2332557134 Status_of_Closed_Loop "闭环算法开启状态";
CM_ SG_ 2332557134 S2A_S7_FullDisChgFlgFromSBMU_14 "满放标志位";
CM_ SG_ 2332557134 S2A_S7_MaxSelfDischgRates_14 "电池簇电芯月自放电率最大值";
CM_ SG_ 2332557134 S2A_S7_MinSelfDischgRates_14 "电池簇电芯月自放电率最小值";
CM_ SG_ 2332557134 S2A_S7_AvgSelfDischgRates_14 "电池簇电芯月自放电率平均值";
CM_ SG_ 2332557134 S2A_S7_SOH_14 "平均SOH ";
CM_ SG_ 2332557135 CRC_S2A_S7_15 "S2A概要数据7 的CRC";
CM_ SG_ 2332557135 BAT_SOC_CorrectState_15 "SOC修正状态（最后一次）";
CM_ SG_ 2332557135 Status_of_Closed_Loop "闭环算法开启状态";
CM_ SG_ 2332557135 S2A_S7_FullDisChgFlgFromSBMU_15 "满放标志位";
CM_ SG_ 2332557135 S2A_S7_MaxSelfDischgRates_15 "电池簇电芯月自放电率最大值";
CM_ SG_ 2332557135 S2A_S7_MinSelfDischgRates_15 "电池簇电芯月自放电率最小值";
CM_ SG_ 2332557135 S2A_S7_AvgSelfDischgRates_15 "电池簇电芯月自放电率平均值";
CM_ SG_ 2332557135 S2A_S7_SOH_15 "平均SOH ";
CM_ SG_ 2332557136 CRC_S2A_S7_16 "S2A概要数据7 的CRC";
CM_ SG_ 2332557136 BAT_SOC_CorrectState_16 "SOC修正状态（最后一次）";
CM_ SG_ 2332557136 Status_of_Closed_Loop "闭环算法开启状态";
CM_ SG_ 2332557136 S2A_S7_FullDisChgFlgFromSBMU_16 "满放标志位";
CM_ SG_ 2332557136 S2A_S7_MaxSelfDischgRates_16 "电池簇电芯月自放电率最大值";
CM_ SG_ 2332557136 S2A_S7_MinSelfDischgRates_16 "电池簇电芯月自放电率最小值";
CM_ SG_ 2332557136 S2A_S7_AvgSelfDischgRates_16 "电池簇电芯月自放电率平均值";
CM_ SG_ 2332557136 S2A_S7_SOH_16 "平均SOH ";
CM_ SG_ 2332557137 CRC_S2A_S7_17 "S2A概要数据7 的CRC";
CM_ SG_ 2332557137 BAT_SOC_CorrectState_17 "SOC修正状态（最后一次）";
CM_ SG_ 2332557137 Status_of_Closed_Loop "闭环算法开启状态";
CM_ SG_ 2332557137 S2A_S7_FullDisChgFlgFromSBMU_17 "满放标志位";
CM_ SG_ 2332557137 S2A_S7_MaxSelfDischgRates_17 "电池簇电芯月自放电率最大值";
CM_ SG_ 2332557137 S2A_S7_MinSelfDischgRates_17 "电池簇电芯月自放电率最小值";
CM_ SG_ 2332557137 S2A_S7_AvgSelfDischgRates_17 "电池簇电芯月自放电率平均值";
CM_ SG_ 2332557137 S2A_S7_SOH_17 "平均SOH ";
CM_ SG_ 2332557138 CRC_S2A_S7_18 "S2A概要数据7 的CRC";
CM_ SG_ 2332557138 BAT_SOC_CorrectState_18 "SOC修正状态（最后一次）";
CM_ SG_ 2332557138 Status_of_Closed_Loop "闭环算法开启状态";
CM_ SG_ 2332557138 S2A_S7_FullDisChgFlgFromSBMU_18 "满放标志位";
CM_ SG_ 2332557138 S2A_S7_MaxSelfDischgRates_18 "电池簇电芯月自放电率最大值";
CM_ SG_ 2332557138 S2A_S7_MinSelfDischgRates_18 "电池簇电芯月自放电率最小值";
CM_ SG_ 2332557138 S2A_S7_AvgSelfDischgRates_18 "电池簇电芯月自放电率平均值";
CM_ SG_ 2332557138 S2A_S7_SOH_18 "平均SOH ";
CM_ SG_ 2332557139 CRC_S2A_S7_19 "S2A概要数据7 的CRC";
CM_ SG_ 2332557139 BAT_SOC_CorrectState_19 "SOC修正状态（最后一次）";
CM_ SG_ 2332557139 Status_of_Closed_Loop "闭环算法开启状态";
CM_ SG_ 2332557139 S2A_S7_FullDisChgFlgFromSBMU_19 "满放标志位";
CM_ SG_ 2332557139 S2A_S7_MaxSelfDischgRates_19 "电池簇电芯月自放电率最大值";
CM_ SG_ 2332557139 S2A_S7_MinSelfDischgRates_19 "电池簇电芯月自放电率最小值";
CM_ SG_ 2332557139 S2A_S7_AvgSelfDischgRates_19 "电池簇电芯月自放电率平均值";
CM_ SG_ 2332557139 S2A_S7_SOH_19 "平均SOH ";
CM_ SG_ 2332557140 CRC_S2A_S7_20 "S2A概要数据7 的CRC";
CM_ SG_ 2332557140 BAT_SOC_CorrectState_20 "SOC修正状态（最后一次）";
CM_ SG_ 2332557140 Status_of_Closed_Loop "闭环算法开启状态";
CM_ SG_ 2332557140 S2A_S7_FullDisChgFlgFromSBMU_20 "满放标志位";
CM_ SG_ 2332557140 S2A_S7_MaxSelfDischgRates_20 "电池簇电芯月自放电率最大值";
CM_ SG_ 2332557140 S2A_S7_MinSelfDischgRates_20 "电池簇电芯月自放电率最小值";
CM_ SG_ 2332557140 S2A_S7_AvgSelfDischgRates_20 "电池簇电芯月自放电率平均值";
CM_ SG_ 2332557140 S2A_S7_SOH_20 "平均SOH ";
CM_ SG_ 2332557141 CRC_S2A_S7_21 "S2A概要数据7 的CRC";
CM_ SG_ 2332557141 BAT_SOC_CorrectState_21 "SOC修正状态（最后一次）";
CM_ SG_ 2332557141 Status_of_Closed_Loop "闭环算法开启状态";
CM_ SG_ 2332557141 S2A_S7_FullDisChgFlgFromSBMU_21 "满放标志位";
CM_ SG_ 2332557141 S2A_S7_MaxSelfDischgRates_21 "电池簇电芯月自放电率最大值";
CM_ SG_ 2332557141 S2A_S7_MinSelfDischgRates_21 "电池簇电芯月自放电率最小值";
CM_ SG_ 2332557141 S2A_S7_AvgSelfDischgRates_21 "电池簇电芯月自放电率平均值";
CM_ SG_ 2332557141 S2A_S7_SOH_21 "平均SOH ";
CM_ SG_ 2332557142 CRC_S2A_S7_22 "S2A概要数据7 的CRC";
CM_ SG_ 2332557142 BAT_SOC_CorrectState_22 "SOC修正状态（最后一次）";
CM_ SG_ 2332557142 Status_of_Closed_Loop "闭环算法开启状态";
CM_ SG_ 2332557142 S2A_S7_FullDisChgFlgFromSBMU_22 "满放标志位";
CM_ SG_ 2332557142 S2A_S7_MaxSelfDischgRates_22 "电池簇电芯月自放电率最大值";
CM_ SG_ 2332557142 S2A_S7_MinSelfDischgRates_22 "电池簇电芯月自放电率最小值";
CM_ SG_ 2332557142 S2A_S7_AvgSelfDischgRates_22 "电池簇电芯月自放电率平均值";
CM_ SG_ 2332557142 S2A_S7_SOH_22 "平均SOH ";
CM_ SG_ 2332557143 CRC_S2A_S7_23 "S2A概要数据7 的CRC";
CM_ SG_ 2332557143 BAT_SOC_CorrectState_23 "SOC修正状态（最后一次）";
CM_ SG_ 2332557143 Status_of_Closed_Loop "闭环算法开启状态";
CM_ SG_ 2332557143 S2A_S7_FullDisChgFlgFromSBMU_23 "满放标志位";
CM_ SG_ 2332557143 S2A_S7_MaxSelfDischgRates_23 "电池簇电芯月自放电率最大值";
CM_ SG_ 2332557143 S2A_S7_MinSelfDischgRates_23 "电池簇电芯月自放电率最小值";
CM_ SG_ 2332557143 S2A_S7_AvgSelfDischgRates_23 "电池簇电芯月自放电率平均值";
CM_ SG_ 2332557143 S2A_S7_SOH_23 "平均SOH ";
CM_ SG_ 2332557144 CRC_S2A_S7_24 "S2A概要数据7 的CRC";
CM_ SG_ 2332557144 BAT_SOC_CorrectState_24 "SOC修正状态（最后一次）";
CM_ SG_ 2332557144 Status_of_Closed_Loop "闭环算法开启状态";
CM_ SG_ 2332557144 S2A_S7_FullDisChgFlgFromSBMU_24 "满放标志位";
CM_ SG_ 2332557144 S2A_S7_MaxSelfDischgRates_24 "电池簇电芯月自放电率最大值";
CM_ SG_ 2332557144 S2A_S7_MinSelfDischgRates_24 "电池簇电芯月自放电率最小值";
CM_ SG_ 2332557144 S2A_S7_AvgSelfDischgRates_24 "电池簇电芯月自放电率平均值";
CM_ SG_ 2332557144 S2A_S7_SOH_24 "平均SOH ";
CM_ SG_ 2332557145 CRC_S2A_S7_25 "S2A概要数据7 的CRC";
CM_ SG_ 2332557145 BAT_SOC_CorrectState_25 "SOC修正状态（最后一次）";
CM_ SG_ 2332557145 Status_of_Closed_Loop "闭环算法开启状态";
CM_ SG_ 2332557145 S2A_S7_FullDisChgFlgFromSBMU_25 "满放标志位";
CM_ SG_ 2332557145 S2A_S7_MaxSelfDischgRates_25 "电池簇电芯月自放电率最大值";
CM_ SG_ 2332557145 S2A_S7_MinSelfDischgRates_25 "电池簇电芯月自放电率最小值";
CM_ SG_ 2332557145 S2A_S7_AvgSelfDischgRates_25 "电池簇电芯月自放电率平均值";
CM_ SG_ 2332557145 S2A_S7_SOH_25 "平均SOH ";
CM_ SG_ 2332557146 CRC_S2A_S7_26 "S2A概要数据7 的CRC";
CM_ SG_ 2332557146 BAT_SOC_CorrectState_26 "SOC修正状态（最后一次）";
CM_ SG_ 2332557146 Status_of_Closed_Loop "闭环算法开启状态";
CM_ SG_ 2332557146 S2A_S7_FullDisChgFlgFromSBMU_26 "满放标志位";
CM_ SG_ 2332557146 S2A_S7_MaxSelfDischgRates_26 "电池簇电芯月自放电率最大值";
CM_ SG_ 2332557146 S2A_S7_MinSelfDischgRates_26 "电池簇电芯月自放电率最小值";
CM_ SG_ 2332557146 S2A_S7_AvgSelfDischgRates_26 "电池簇电芯月自放电率平均值";
CM_ SG_ 2332557146 S2A_S7_SOH_26 "平均SOH ";
CM_ SG_ 2332557147 CRC_S2A_S7_27 "S2A概要数据7 的CRC";
CM_ SG_ 2332557147 BAT_SOC_CorrectState_27 "SOC修正状态（最后一次）";
CM_ SG_ 2332557147 Status_of_Closed_Loop "闭环算法开启状态";
CM_ SG_ 2332557147 S2A_S7_FullDisChgFlgFromSBMU_27 "满放标志位";
CM_ SG_ 2332557147 S2A_S7_MaxSelfDischgRates_27 "电池簇电芯月自放电率最大值";
CM_ SG_ 2332557147 S2A_S7_MinSelfDischgRates_27 "电池簇电芯月自放电率最小值";
CM_ SG_ 2332557147 S2A_S7_AvgSelfDischgRates_27 "电池簇电芯月自放电率平均值";
CM_ SG_ 2332557147 S2A_S7_SOH_27 "平均SOH ";
CM_ SG_ 2332557148 CRC_S2A_S7_28 "S2A概要数据7 的CRC";
CM_ SG_ 2332557148 BAT_SOC_CorrectState_28 "SOC修正状态（最后一次）";
CM_ SG_ 2332557148 Status_of_Closed_Loop "闭环算法开启状态";
CM_ SG_ 2332557148 S2A_S7_FullDisChgFlgFromSBMU_28 "满放标志位";
CM_ SG_ 2332557148 S2A_S7_MaxSelfDischgRates_28 "电池簇电芯月自放电率最大值";
CM_ SG_ 2332557148 S2A_S7_MinSelfDischgRates_28 "电池簇电芯月自放电率最小值";
CM_ SG_ 2332557148 S2A_S7_AvgSelfDischgRates_28 "电池簇电芯月自放电率平均值";
CM_ SG_ 2332557148 S2A_S7_SOH_28 "平均SOH ";
CM_ SG_ 2332557149 CRC_S2A_S7_29 "S2A概要数据7 的CRC";
CM_ SG_ 2332557149 BAT_SOC_CorrectState_29 "SOC修正状态（最后一次）";
CM_ SG_ 2332557149 Status_of_Closed_Loop "闭环算法开启状态";
CM_ SG_ 2332557149 S2A_S7_FullDisChgFlgFromSBMU_29 "满放标志位";
CM_ SG_ 2332557149 S2A_S7_MaxSelfDischgRates_29 "电池簇电芯月自放电率最大值";
CM_ SG_ 2332557149 S2A_S7_MinSelfDischgRates_29 "电池簇电芯月自放电率最小值";
CM_ SG_ 2332557149 S2A_S7_AvgSelfDischgRates_29 "电池簇电芯月自放电率平均值";
CM_ SG_ 2332557149 S2A_S7_SOH_29 "平均SOH ";
CM_ SG_ 2332557150 CRC_S2A_S7_30 "S2A概要数据7 的CRC";
CM_ SG_ 2332557150 BAT_SOC_CorrectState_30 "SOC修正状态（最后一次）";
CM_ SG_ 2332557150 Status_of_Closed_Loop "闭环算法开启状态";
CM_ SG_ 2332557150 S2A_S7_FullDisChgFlgFromSBMU_30 "满放标志位";
CM_ SG_ 2332557150 S2A_S7_MaxSelfDischgRates_30 "电池簇电芯月自放电率最大值";
CM_ SG_ 2332557150 S2A_S7_MinSelfDischgRates_30 "电池簇电芯月自放电率最小值";
CM_ SG_ 2332557150 S2A_S7_AvgSelfDischgRates_30 "电池簇电芯月自放电率平均值";
CM_ SG_ 2332557150 S2A_S7_SOH_30 "平均SOH ";
CM_ SG_ 2332557151 CRC_S2A_S7_31 "S2A概要数据7 的CRC";
CM_ SG_ 2332557151 BAT_SOC_CorrectState_31 "SOC修正状态（最后一次）";
CM_ SG_ 2332557151 Status_of_Closed_Loop "闭环算法开启状态";
CM_ SG_ 2332557151 S2A_S7_FullDisChgFlgFromSBMU_31 "满放标志位";
CM_ SG_ 2332557151 S2A_S7_MaxSelfDischgRates_31 "电池簇电芯月自放电率最大值";
CM_ SG_ 2332557151 S2A_S7_MinSelfDischgRates_31 "电池簇电芯月自放电率最小值";
CM_ SG_ 2332557151 S2A_S7_AvgSelfDischgRates_31 "电池簇电芯月自放电率平均值";
CM_ SG_ 2332557151 S2A_S7_SOH_31 "平均SOH ";
CM_ SG_ 2332557152 CRC_S2A_S7_32 "S2A概要数据7 的CRC";
CM_ SG_ 2332557152 BAT_SOC_CorrectState_32 "SOC修正状态（最后一次）";
CM_ SG_ 2332557152 Status_of_Closed_Loop "闭环算法开启状态";
CM_ SG_ 2332557152 S2A_S7_FullDisChgFlgFromSBMU_32 "满放标志位";
CM_ SG_ 2332557152 S2A_S7_MaxSelfDischgRates_32 "电池簇电芯月自放电率最大值";
CM_ SG_ 2332557152 S2A_S7_MinSelfDischgRates_32 "电池簇电芯月自放电率最小值";
CM_ SG_ 2332557152 S2A_S7_AvgSelfDischgRates_32 "电池簇电芯月自放电率平均值";
CM_ SG_ 2332557152 S2A_S7_SOH_32 "平均SOH ";
VAL_ 2332491585 SBMU_Evn_T1_01 204 "干接点使用/未作温度采样使用" 205 "无效" ;
VAL_ 2332491585 SBMU_Evn_T2_01 204 "干接点使用/未作温度采样使用" 205 "无效" ;
VAL_ 2332491585 SBMU_Evn_T3_01 204 "干接点使用/未作温度采样使用" 205 "无效" ;
VAL_ 2332491585 S2A_STofCSCAutoCoding_01 0 "Initial" 1 "Successful" 2 "Failed" 3 "In Coding process" 4 "No Coding required" ;
VAL_ 2332491586 SBMU_Evn_T1_02 204 "干接点使用/未作温度采样使用" 205 "无效" ;
VAL_ 2332491586 SBMU_Evn_T2_02 204 "干接点使用/未作温度采样使用" 205 "无效" ;
VAL_ 2332491586 SBMU_Evn_T3_02 204 "干接点使用/未作温度采样使用" 205 "无效" ;
VAL_ 2332491586 S2A_STofCSCAutoCoding_02 0 "Initial" 1 "Successful" 2 "Failed" 3 "In Coding process" 4 "No Coding required" ;
VAL_ 2332491587 SBMU_Evn_T1_03 204 "干接点使用/未作温度采样使用" 205 "无效" ;
VAL_ 2332491587 SBMU_Evn_T2_03 204 "干接点使用/未作温度采样使用" 205 "无效" ;
VAL_ 2332491587 SBMU_Evn_T3_03 204 "干接点使用/未作温度采样使用" 205 "无效" ;
VAL_ 2332491587 S2A_STofCSCAutoCoding_03 0 "Initial" 1 "Successful" 2 "Failed" 3 "In Coding process" 4 "No Coding required" ;
VAL_ 2332491588 SBMU_Evn_T1_04 204 "干接点使用/未作温度采样使用" 205 "无效" ;
VAL_ 2332491588 SBMU_Evn_T2_04 204 "干接点使用/未作温度采样使用" 205 "无效" ;
VAL_ 2332491588 SBMU_Evn_T3_04 204 "干接点使用/未作温度采样使用" 205 "无效" ;
VAL_ 2332491588 S2A_STofCSCAutoCoding_04 0 "Initial" 1 "Successful" 2 "Failed" 3 "In Coding process" 4 "No Coding required" ;
VAL_ 2332491589 SBMU_Evn_T1_05 204 "干接点使用/未作温度采样使用" 205 "无效" ;
VAL_ 2332491589 SBMU_Evn_T2_05 204 "干接点使用/未作温度采样使用" 205 "无效" ;
VAL_ 2332491589 SBMU_Evn_T3_05 204 "干接点使用/未作温度采样使用" 205 "无效" ;
VAL_ 2332491589 S2A_STofCSCAutoCoding_05 0 "Initial" 1 "Successful" 2 "Failed" 3 "In Coding process" 4 "No Coding required" ;
VAL_ 2332491590 SBMU_Evn_T1_06 204 "干接点使用/未作温度采样使用" 205 "无效" ;
VAL_ 2332491590 SBMU_Evn_T2_06 204 "干接点使用/未作温度采样使用" 205 "无效" ;
VAL_ 2332491590 SBMU_Evn_T3_06 204 "干接点使用/未作温度采样使用" 205 "无效" ;
VAL_ 2332491590 S2A_STofCSCAutoCoding_06 0 "Initial" 1 "Successful" 2 "Failed" 3 "In Coding process" 4 "No Coding required" ;
VAL_ 2332491591 SBMU_Evn_T1_07 204 "干接点使用/未作温度采样使用" 205 "无效" ;
VAL_ 2332491591 SBMU_Evn_T2_07 204 "干接点使用/未作温度采样使用" 205 "无效" ;
VAL_ 2332491591 SBMU_Evn_T3_07 204 "干接点使用/未作温度采样使用" 205 "无效" ;
VAL_ 2332491591 S2A_STofCSCAutoCoding_07 0 "Initial" 1 "Successful" 2 "Failed" 3 "In Coding process" 4 "No Coding required" ;
VAL_ 2332491592 SBMU_Evn_T1_08 204 "干接点使用/未作温度采样使用" 205 "无效" ;
VAL_ 2332491592 SBMU_Evn_T2_08 204 "干接点使用/未作温度采样使用" 205 "无效" ;
VAL_ 2332491592 SBMU_Evn_T3_08 204 "干接点使用/未作温度采样使用" 205 "无效" ;
VAL_ 2332491592 S2A_STofCSCAutoCoding_08 0 "Initial" 1 "Successful" 2 "Failed" 3 "In Coding process" 4 "No Coding required" ;
VAL_ 2332491593 SBMU_Evn_T1_09 204 "干接点使用/未作温度采样使用" 205 "无效" ;
VAL_ 2332491593 SBMU_Evn_T2_09 204 "干接点使用/未作温度采样使用" 205 "无效" ;
VAL_ 2332491593 SBMU_Evn_T3_09 204 "干接点使用/未作温度采样使用" 205 "无效" ;
VAL_ 2332491593 S2A_STofCSCAutoCoding_09 0 "Initial" 1 "Successful" 2 "Failed" 3 "In Coding process" 4 "No Coding required" ;
VAL_ 2332491594 SBMU_Evn_T1_10 204 "干接点使用/未作温度采样使用" 205 "无效" ;
VAL_ 2332491594 SBMU_Evn_T2_10 204 "干接点使用/未作温度采样使用" 205 "无效" ;
VAL_ 2332491594 SBMU_Evn_T3_10 204 "干接点使用/未作温度采样使用" 205 "无效" ;
VAL_ 2332491594 S2A_STofCSCAutoCoding_10 0 "Initial" 1 "Successful" 2 "Failed" 3 "In Coding process" 4 "No Coding required" ;
VAL_ 2332491595 SBMU_Evn_T1_11 204 "干接点使用/未作温度采样使用" 205 "无效" ;
VAL_ 2332491595 SBMU_Evn_T2_11 204 "干接点使用/未作温度采样使用" 205 "无效" ;
VAL_ 2332491595 SBMU_Evn_T3_11 204 "干接点使用/未作温度采样使用" 205 "无效" ;
VAL_ 2332491595 S2A_STofCSCAutoCoding_11 0 "Initial" 1 "Successful" 2 "Failed" 3 "In Coding process" 4 "No Coding required" ;
VAL_ 2332491596 SBMU_Evn_T1_12 204 "干接点使用/未作温度采样使用" 205 "无效" ;
VAL_ 2332491596 SBMU_Evn_T2_12 204 "干接点使用/未作温度采样使用" 205 "无效" ;
VAL_ 2332491596 SBMU_Evn_T3_12 204 "干接点使用/未作温度采样使用" 205 "无效" ;
VAL_ 2332491596 S2A_STofCSCAutoCoding_12 0 "Initial" 1 "Successful" 2 "Failed" 3 "In Coding process" 4 "No Coding required" ;
VAL_ 2332491597 SBMU_Evn_T1_13 204 "干接点使用/未作温度采样使用" 205 "无效" ;
VAL_ 2332491597 SBMU_Evn_T2_13 204 "干接点使用/未作温度采样使用" 205 "无效" ;
VAL_ 2332491597 SBMU_Evn_T3_13 204 "干接点使用/未作温度采样使用" 205 "无效" ;
VAL_ 2332491597 S2A_STofCSCAutoCoding_13 0 "Initial" 1 "Successful" 2 "Failed" 3 "In Coding process" 4 "No Coding required" ;
VAL_ 2332491598 SBMU_Evn_T1_14 204 "干接点使用/未作温度采样使用" 205 "无效" ;
VAL_ 2332491598 SBMU_Evn_T2_14 204 "干接点使用/未作温度采样使用" 205 "无效" ;
VAL_ 2332491598 SBMU_Evn_T3_14 204 "干接点使用/未作温度采样使用" 205 "无效" ;
VAL_ 2332491598 S2A_STofCSCAutoCoding_14 0 "Initial" 1 "Successful" 2 "Failed" 3 "In Coding process" 4 "No Coding required" ;
VAL_ 2332491599 SBMU_Evn_T1_15 204 "干接点使用/未作温度采样使用" 205 "无效" ;
VAL_ 2332491599 SBMU_Evn_T2_15 204 "干接点使用/未作温度采样使用" 205 "无效" ;
VAL_ 2332491599 SBMU_Evn_T3_15 204 "干接点使用/未作温度采样使用" 205 "无效" ;
VAL_ 2332491599 S2A_STofCSCAutoCoding_15 0 "Initial" 1 "Successful" 2 "Failed" 3 "In Coding process" 4 "No Coding required" ;
VAL_ 2332491600 SBMU_Evn_T1_16 204 "干接点使用/未作温度采样使用" 205 "无效" ;
VAL_ 2332491600 SBMU_Evn_T2_16 204 "干接点使用/未作温度采样使用" 205 "无效" ;
VAL_ 2332491600 SBMU_Evn_T3_16 204 "干接点使用/未作温度采样使用" 205 "无效" ;
VAL_ 2332491600 S2A_STofCSCAutoCoding_16 0 "Initial" 1 "Successful" 2 "Failed" 3 "In Coding process" 4 "No Coding required" ;
VAL_ 2332491601 SBMU_Evn_T1_17 204 "干接点使用/未作温度采样使用" 205 "无效" ;
VAL_ 2332491601 SBMU_Evn_T2_17 204 "干接点使用/未作温度采样使用" 205 "无效" ;
VAL_ 2332491601 SBMU_Evn_T3_17 204 "干接点使用/未作温度采样使用" 205 "无效" ;
VAL_ 2332491601 S2A_STofCSCAutoCoding_17 0 "Initial" 1 "Successful" 2 "Failed" 3 "In Coding process" 4 "No Coding required" ;
VAL_ 2332491602 SBMU_Evn_T1_18 204 "干接点使用/未作温度采样使用" 205 "无效" ;
VAL_ 2332491602 SBMU_Evn_T2_18 204 "干接点使用/未作温度采样使用" 205 "无效" ;
VAL_ 2332491602 SBMU_Evn_T3_18 204 "干接点使用/未作温度采样使用" 205 "无效" ;
VAL_ 2332491602 S2A_STofCSCAutoCoding_18 0 "Initial" 1 "Successful" 2 "Failed" 3 "In Coding process" 4 "No Coding required" ;
VAL_ 2332491603 SBMU_Evn_T1_19 204 "干接点使用/未作温度采样使用" 205 "无效" ;
VAL_ 2332491603 SBMU_Evn_T2_19 204 "干接点使用/未作温度采样使用" 205 "无效" ;
VAL_ 2332491603 SBMU_Evn_T3_19 204 "干接点使用/未作温度采样使用" 205 "无效" ;
VAL_ 2332491603 S2A_STofCSCAutoCoding_19 0 "Initial" 1 "Successful" 2 "Failed" 3 "In Coding process" 4 "No Coding required" ;
VAL_ 2332491604 SBMU_Evn_T1_20 204 "干接点使用/未作温度采样使用" 205 "无效" ;
VAL_ 2332491604 SBMU_Evn_T2_20 204 "干接点使用/未作温度采样使用" 205 "无效" ;
VAL_ 2332491604 SBMU_Evn_T3_20 204 "干接点使用/未作温度采样使用" 205 "无效" ;
VAL_ 2332491604 S2A_STofCSCAutoCoding_20 0 "Initial" 1 "Successful" 2 "Failed" 3 "In Coding process" 4 "No Coding required" ;
VAL_ 2332491605 SBMU_Evn_T1_21 204 "干接点使用/未作温度采样使用" 205 "无效" ;
VAL_ 2332491605 SBMU_Evn_T2_21 204 "干接点使用/未作温度采样使用" 205 "无效" ;
VAL_ 2332491605 SBMU_Evn_T3_21 204 "干接点使用/未作温度采样使用" 205 "无效" ;
VAL_ 2332491605 S2A_STofCSCAutoCoding_21 0 "Initial" 1 "Successful" 2 "Failed" 3 "In Coding process" 4 "No Coding required" ;
VAL_ 2332491606 SBMU_Evn_T1_22 204 "干接点使用/未作温度采样使用" 205 "无效" ;
VAL_ 2332491606 SBMU_Evn_T2_22 204 "干接点使用/未作温度采样使用" 205 "无效" ;
VAL_ 2332491606 SBMU_Evn_T3_22 204 "干接点使用/未作温度采样使用" 205 "无效" ;
VAL_ 2332491606 S2A_STofCSCAutoCoding_22 0 "Initial" 1 "Successful" 2 "Failed" 3 "In Coding process" 4 "No Coding required" ;
VAL_ 2332491607 SBMU_Evn_T1_23 204 "干接点使用/未作温度采样使用" 205 "无效" ;
VAL_ 2332491607 SBMU_Evn_T2_23 204 "干接点使用/未作温度采样使用" 205 "无效" ;
VAL_ 2332491607 SBMU_Evn_T3_23 204 "干接点使用/未作温度采样使用" 205 "无效" ;
VAL_ 2332491607 S2A_STofCSCAutoCoding_23 0 "Initial" 1 "Successful" 2 "Failed" 3 "In Coding process" 4 "No Coding required" ;
VAL_ 2332491608 SBMU_Evn_T1_24 204 "干接点使用/未作温度采样使用" 205 "无效" ;
VAL_ 2332491608 SBMU_Evn_T2_24 204 "干接点使用/未作温度采样使用" 205 "无效" ;
VAL_ 2332491608 SBMU_Evn_T3_24 204 "干接点使用/未作温度采样使用" 205 "无效" ;
VAL_ 2332491608 S2A_STofCSCAutoCoding_24 0 "Initial" 1 "Successful" 2 "Failed" 3 "In Coding process" 4 "No Coding required" ;
VAL_ 2332491609 SBMU_Evn_T1_25 204 "干接点使用/未作温度采样使用" 205 "无效" ;
VAL_ 2332491609 SBMU_Evn_T2_25 204 "干接点使用/未作温度采样使用" 205 "无效" ;
VAL_ 2332491609 SBMU_Evn_T3_25 204 "干接点使用/未作温度采样使用" 205 "无效" ;
VAL_ 2332491609 S2A_STofCSCAutoCoding_25 0 "Initial" 1 "Successful" 2 "Failed" 3 "In Coding process" 4 "No Coding required" ;
VAL_ 2332491610 SBMU_Evn_T1_26 204 "干接点使用/未作温度采样使用" 205 "无效" ;
VAL_ 2332491610 SBMU_Evn_T2_26 204 "干接点使用/未作温度采样使用" 205 "无效" ;
VAL_ 2332491610 SBMU_Evn_T3_26 204 "干接点使用/未作温度采样使用" 205 "无效" ;
VAL_ 2332491610 S2A_STofCSCAutoCoding_26 0 "Initial" 1 "Successful" 2 "Failed" 3 "In Coding process" 4 "No Coding required" ;
VAL_ 2332491611 SBMU_Evn_T1_27 204 "干接点使用/未作温度采样使用" 205 "无效" ;
VAL_ 2332491611 SBMU_Evn_T2_27 204 "干接点使用/未作温度采样使用" 205 "无效" ;
VAL_ 2332491611 SBMU_Evn_T3_27 204 "干接点使用/未作温度采样使用" 205 "无效" ;
VAL_ 2332491611 S2A_STofCSCAutoCoding_27 0 "Initial" 1 "Successful" 2 "Failed" 3 "In Coding process" 4 "No Coding required" ;
VAL_ 2332491612 SBMU_Evn_T1_28 204 "干接点使用/未作温度采样使用" 205 "无效" ;
VAL_ 2332491612 SBMU_Evn_T2_28 204 "干接点使用/未作温度采样使用" 205 "无效" ;
VAL_ 2332491612 SBMU_Evn_T3_28 204 "干接点使用/未作温度采样使用" 205 "无效" ;
VAL_ 2332491612 S2A_STofCSCAutoCoding_28 0 "Initial" 1 "Successful" 2 "Failed" 3 "In Coding process" 4 "No Coding required" ;
VAL_ 2332491613 SBMU_Evn_T1_29 204 "干接点使用/未作温度采样使用" 205 "无效" ;
VAL_ 2332491613 SBMU_Evn_T2_29 204 "干接点使用/未作温度采样使用" 205 "无效" ;
VAL_ 2332491613 SBMU_Evn_T3_29 204 "干接点使用/未作温度采样使用" 205 "无效" ;
VAL_ 2332491613 S2A_STofCSCAutoCoding_29 0 "Initial" 1 "Successful" 2 "Failed" 3 "In Coding process" 4 "No Coding required" ;
VAL_ 2332491614 SBMU_Evn_T1_30 204 "干接点使用/未作温度采样使用" 205 "无效" ;
VAL_ 2332491614 SBMU_Evn_T2_30 204 "干接点使用/未作温度采样使用" 205 "无效" ;
VAL_ 2332491614 SBMU_Evn_T3_30 204 "干接点使用/未作温度采样使用" 205 "无效" ;
VAL_ 2332491614 S2A_STofCSCAutoCoding_30 0 "Initial" 1 "Successful" 2 "Failed" 3 "In Coding process" 4 "No Coding required" ;
VAL_ 2332491615 SBMU_Evn_T1_31 204 "干接点使用/未作温度采样使用" 205 "无效" ;
VAL_ 2332491615 SBMU_Evn_T2_31 204 "干接点使用/未作温度采样使用" 205 "无效" ;
VAL_ 2332491615 SBMU_Evn_T3_31 204 "干接点使用/未作温度采样使用" 205 "无效" ;
VAL_ 2332491615 S2A_STofCSCAutoCoding_31 0 "Initial" 1 "Successful" 2 "Failed" 3 "In Coding process" 4 "No Coding required" ;
VAL_ 2332491616 SBMU_Evn_T1_32 204 "干接点使用/未作温度采样使用" 205 "无效" ;
VAL_ 2332491616 SBMU_Evn_T2_32 204 "干接点使用/未作温度采样使用" 205 "无效" ;
VAL_ 2332491616 SBMU_Evn_T3_32 204 "干接点使用/未作温度采样使用" 205 "无效" ;
VAL_ 2332491616 S2A_STofCSCAutoCoding_32 0 "Initial" 1 "Successful" 2 "Failed" 3 "In Coding process" 4 "No Coding required" ;
VAL_ 2332491617 SBMU_Evn_T1_33 204 "干接点使用/未作温度采样使用" 205 "无效" ;
VAL_ 2332491617 SBMU_Evn_T2_33 204 "干接点使用/未作温度采样使用" 205 "无效" ;
VAL_ 2332491617 SBMU_Evn_T3_33 204 "干接点使用/未作温度采样使用" 205 "无效" ;
VAL_ 2332491617 S2A_STofCSCAutoCoding_33 0 "Initial" 1 "Successful" 2 "Failed" 3 "In Coding process" 4 "No Coding required" ;
VAL_ 2332491618 SBMU_Evn_T1_34 204 "干接点使用/未作温度采样使用" 205 "无效" ;
VAL_ 2332491618 SBMU_Evn_T2_34 204 "干接点使用/未作温度采样使用" 205 "无效" ;
VAL_ 2332491618 SBMU_Evn_T3_34 204 "干接点使用/未作温度采样使用" 205 "无效" ;
VAL_ 2332491618 S2A_STofCSCAutoCoding_34 0 "Initial" 1 "Successful" 2 "Failed" 3 "In Coding process" 4 "No Coding required" ;
VAL_ 2332491619 SBMU_Evn_T1_35 204 "干接点使用/未作温度采样使用" 205 "无效" ;
VAL_ 2332491619 SBMU_Evn_T2_35 204 "干接点使用/未作温度采样使用" 205 "无效" ;
VAL_ 2332491619 SBMU_Evn_T3_35 204 "干接点使用/未作温度采样使用" 205 "无效" ;
VAL_ 2332491619 S2A_STofCSCAutoCoding_35 0 "Initial" 1 "Successful" 2 "Failed" 3 "In Coding process" 4 "No Coding required" ;
VAL_ 2332491620 SBMU_Evn_T1_36 204 "干接点使用/未作温度采样使用" 205 "无效" ;
VAL_ 2332491620 SBMU_Evn_T2_36 204 "干接点使用/未作温度采样使用" 205 "无效" ;
VAL_ 2332491620 SBMU_Evn_T3_36 204 "干接点使用/未作温度采样使用" 205 "无效" ;
VAL_ 2332491620 S2A_STofCSCAutoCoding_36 0 "Initial" 1 "Successful" 2 "Failed" 3 "In Coding process" 4 "No Coding required" ;
VAL_ 2332491621 SBMU_Evn_T1_37 204 "干接点使用/未作温度采样使用" 205 "无效" ;
VAL_ 2332491621 SBMU_Evn_T2_37 204 "干接点使用/未作温度采样使用" 205 "无效" ;
VAL_ 2332491621 SBMU_Evn_T3_37 204 "干接点使用/未作温度采样使用" 205 "无效" ;
VAL_ 2332491621 S2A_STofCSCAutoCoding_37 0 "Initial" 1 "Successful" 2 "Failed" 3 "In Coding process" 4 "No Coding required" ;
VAL_ 2332491622 SBMU_Evn_T1_38 204 "干接点使用/未作温度采样使用" 205 "无效" ;
VAL_ 2332491622 SBMU_Evn_T2_38 204 "干接点使用/未作温度采样使用" 205 "无效" ;
VAL_ 2332491622 SBMU_Evn_T3_38 204 "干接点使用/未作温度采样使用" 205 "无效" ;
VAL_ 2332491622 S2A_STofCSCAutoCoding_38 0 "Initial" 1 "Successful" 2 "Failed" 3 "In Coding process" 4 "No Coding required" ;
VAL_ 2332491623 SBMU_Evn_T1_39 204 "干接点使用/未作温度采样使用" 205 "无效" ;
VAL_ 2332491623 SBMU_Evn_T2_39 204 "干接点使用/未作温度采样使用" 205 "无效" ;
VAL_ 2332491623 SBMU_Evn_T3_39 204 "干接点使用/未作温度采样使用" 205 "无效" ;
VAL_ 2332491623 S2A_STofCSCAutoCoding_39 0 "Initial" 1 "Successful" 2 "Failed" 3 "In Coding process" 4 "No Coding required" ;
VAL_ 2332491624 SBMU_Evn_T1_40 204 "干接点使用/未作温度采样使用" 205 "无效" ;
VAL_ 2332491624 SBMU_Evn_T2_40 204 "干接点使用/未作温度采样使用" 205 "无效" ;
VAL_ 2332491624 SBMU_Evn_T3_40 204 "干接点使用/未作温度采样使用" 205 "无效" ;
VAL_ 2332491624 S2A_STofCSCAutoCoding_40 0 "Initial" 1 "Successful" 2 "Failed" 3 "In Coding process" 4 "No Coding required" ;
VAL_ 2332491625 SBMU_Evn_T1_41 204 "干接点使用/未作温度采样使用" 205 "无效" ;
VAL_ 2332491625 SBMU_Evn_T2_41 204 "干接点使用/未作温度采样使用" 205 "无效" ;
VAL_ 2332491625 SBMU_Evn_T3_41 204 "干接点使用/未作温度采样使用" 205 "无效" ;
VAL_ 2332491625 S2A_STofCSCAutoCoding_41 0 "Initial" 1 "Successful" 2 "Failed" 3 "In Coding process" 4 "No Coding required" ;
VAL_ 2332491626 SBMU_Evn_T1_42 204 "干接点使用/未作温度采样使用" 205 "无效" ;
VAL_ 2332491626 SBMU_Evn_T2_42 204 "干接点使用/未作温度采样使用" 205 "无效" ;
VAL_ 2332491626 SBMU_Evn_T3_42 204 "干接点使用/未作温度采样使用" 205 "无效" ;
VAL_ 2332491626 S2A_STofCSCAutoCoding_42 0 "Initial" 1 "Successful" 2 "Failed" 3 "In Coding process" 4 "No Coding required" ;
VAL_ 2332491627 SBMU_Evn_T1_43 204 "干接点使用/未作温度采样使用" 205 "无效" ;
VAL_ 2332491627 SBMU_Evn_T2_43 204 "干接点使用/未作温度采样使用" 205 "无效" ;
VAL_ 2332491627 SBMU_Evn_T3_43 204 "干接点使用/未作温度采样使用" 205 "无效" ;
VAL_ 2332491627 S2A_STofCSCAutoCoding_43 0 "Initial" 1 "Successful" 2 "Failed" 3 "In Coding process" 4 "No Coding required" ;
VAL_ 2332491628 SBMU_Evn_T1_44 204 "干接点使用/未作温度采样使用" 205 "无效" ;
VAL_ 2332491628 SBMU_Evn_T2_44 204 "干接点使用/未作温度采样使用" 205 "无效" ;
VAL_ 2332491628 SBMU_Evn_T3_44 204 "干接点使用/未作温度采样使用" 205 "无效" ;
VAL_ 2332491628 S2A_STofCSCAutoCoding_44 0 "Initial" 1 "Successful" 2 "Failed" 3 "In Coding process" 4 "No Coding required" ;
VAL_ 2332491629 SBMU_Evn_T1_45 204 "干接点使用/未作温度采样使用" 205 "无效" ;
VAL_ 2332491629 SBMU_Evn_T2_45 204 "干接点使用/未作温度采样使用" 205 "无效" ;
VAL_ 2332491629 SBMU_Evn_T3_45 204 "干接点使用/未作温度采样使用" 205 "无效" ;
VAL_ 2332491629 S2A_STofCSCAutoCoding_45 0 "Initial" 1 "Successful" 2 "Failed" 3 "In Coding process" 4 "No Coding required" ;
VAL_ 2332491630 SBMU_Evn_T1_46 204 "干接点使用/未作温度采样使用" 205 "无效" ;
VAL_ 2332491630 SBMU_Evn_T2_46 204 "干接点使用/未作温度采样使用" 205 "无效" ;
VAL_ 2332491630 SBMU_Evn_T3_46 204 "干接点使用/未作温度采样使用" 205 "无效" ;
VAL_ 2332491630 S2A_STofCSCAutoCoding_46 0 "Initial" 1 "Successful" 2 "Failed" 3 "In Coding process" 4 "No Coding required" ;
VAL_ 2332491631 SBMU_Evn_T1_47 204 "干接点使用/未作温度采样使用" 205 "无效" ;
VAL_ 2332491631 SBMU_Evn_T2_47 204 "干接点使用/未作温度采样使用" 205 "无效" ;
VAL_ 2332491631 SBMU_Evn_T3_47 204 "干接点使用/未作温度采样使用" 205 "无效" ;
VAL_ 2332491631 S2A_STofCSCAutoCoding_47 0 "Initial" 1 "Successful" 2 "Failed" 3 "In Coding process" 4 "No Coding required" ;
VAL_ 2332491632 SBMU_Evn_T1_48 204 "干接点使用/未作温度采样使用" 205 "无效" ;
VAL_ 2332491632 SBMU_Evn_T2_48 204 "干接点使用/未作温度采样使用" 205 "无效" ;
VAL_ 2332491632 SBMU_Evn_T3_48 204 "干接点使用/未作温度采样使用" 205 "无效" ;
VAL_ 2332491632 S2A_STofCSCAutoCoding_48 0 "Initial" 1 "Successful" 2 "Failed" 3 "In Coding process" 4 "No Coding required" ;
VAL_ 2332491633 SBMU_Evn_T1_49 204 "干接点使用/未作温度采样使用" 205 "无效" ;
VAL_ 2332491633 SBMU_Evn_T2_49 204 "干接点使用/未作温度采样使用" 205 "无效" ;
VAL_ 2332491633 SBMU_Evn_T3_49 204 "干接点使用/未作温度采样使用" 205 "无效" ;
VAL_ 2332491633 S2A_STofCSCAutoCoding_49 0 "Initial" 1 "Successful" 2 "Failed" 3 "In Coding process" 4 "No Coding required" ;
VAL_ 2332491634 SBMU_Evn_T1_50 204 "干接点使用/未作温度采样使用" 205 "无效" ;
VAL_ 2332491634 SBMU_Evn_T2_50 204 "干接点使用/未作温度采样使用" 205 "无效" ;
VAL_ 2332491634 SBMU_Evn_T3_50 204 "干接点使用/未作温度采样使用" 205 "无效" ;
VAL_ 2332491634 S2A_STofCSCAutoCoding_50 0 "Initial" 1 "Successful" 2 "Failed" 3 "In Coding process" 4 "No Coding required" ;
VAL_ 2332491635 SBMU_Evn_T1_51 204 "干接点使用/未作温度采样使用" 205 "无效" ;
VAL_ 2332491635 SBMU_Evn_T2_51 204 "干接点使用/未作温度采样使用" 205 "无效" ;
VAL_ 2332491635 SBMU_Evn_T3_51 204 "干接点使用/未作温度采样使用" 205 "无效" ;
VAL_ 2332491635 S2A_STofCSCAutoCoding_51 0 "Initial" 1 "Successful" 2 "Failed" 3 "In Coding process" 4 "No Coding required" ;
VAL_ 2332491636 SBMU_Evn_T1_52 204 "干接点使用/未作温度采样使用" 205 "无效" ;
VAL_ 2332491636 SBMU_Evn_T2_52 204 "干接点使用/未作温度采样使用" 205 "无效" ;
VAL_ 2332491636 SBMU_Evn_T3_52 204 "干接点使用/未作温度采样使用" 205 "无效" ;
VAL_ 2332491636 S2A_STofCSCAutoCoding_52 0 "Initial" 1 "Successful" 2 "Failed" 3 "In Coding process" 4 "No Coding required" ;
VAL_ 2332491637 SBMU_Evn_T1_53 204 "干接点使用/未作温度采样使用" 205 "无效" ;
VAL_ 2332491637 SBMU_Evn_T2_53 204 "干接点使用/未作温度采样使用" 205 "无效" ;
VAL_ 2332491637 SBMU_Evn_T3_53 204 "干接点使用/未作温度采样使用" 205 "无效" ;
VAL_ 2332491637 S2A_STofCSCAutoCoding_53 0 "Initial" 1 "Successful" 2 "Failed" 3 "In Coding process" 4 "No Coding required" ;
VAL_ 2332491638 SBMU_Evn_T1_54 204 "干接点使用/未作温度采样使用" 205 "无效" ;
VAL_ 2332491638 SBMU_Evn_T2_54 204 "干接点使用/未作温度采样使用" 205 "无效" ;
VAL_ 2332491638 SBMU_Evn_T3_54 204 "干接点使用/未作温度采样使用" 205 "无效" ;
VAL_ 2332491638 S2A_STofCSCAutoCoding_54 0 "Initial" 1 "Successful" 2 "Failed" 3 "In Coding process" 4 "No Coding required" ;
VAL_ 2332491639 SBMU_Evn_T1_55 204 "干接点使用/未作温度采样使用" 205 "无效" ;
VAL_ 2332491639 SBMU_Evn_T2_55 204 "干接点使用/未作温度采样使用" 205 "无效" ;
VAL_ 2332491639 SBMU_Evn_T3_55 204 "干接点使用/未作温度采样使用" 205 "无效" ;
VAL_ 2332491639 S2A_STofCSCAutoCoding_55 0 "Initial" 1 "Successful" 2 "Failed" 3 "In Coding process" 4 "No Coding required" ;
VAL_ 2332491640 SBMU_Evn_T1_56 204 "干接点使用/未作温度采样使用" 205 "无效" ;
VAL_ 2332491640 SBMU_Evn_T2_56 204 "干接点使用/未作温度采样使用" 205 "无效" ;
VAL_ 2332491640 SBMU_Evn_T3_56 204 "干接点使用/未作温度采样使用" 205 "无效" ;
VAL_ 2332491640 S2A_STofCSCAutoCoding_56 0 "Initial" 1 "Successful" 2 "Failed" 3 "In Coding process" 4 "No Coding required" ;
VAL_ 2332491641 SBMU_Evn_T1_57 204 "干接点使用/未作温度采样使用" 205 "无效" ;
VAL_ 2332491641 SBMU_Evn_T2_57 204 "干接点使用/未作温度采样使用" 205 "无效" ;
VAL_ 2332491641 SBMU_Evn_T3_57 204 "干接点使用/未作温度采样使用" 205 "无效" ;
VAL_ 2332491641 S2A_STofCSCAutoCoding_57 0 "Initial" 1 "Successful" 2 "Failed" 3 "In Coding process" 4 "No Coding required" ;
VAL_ 2332491642 SBMU_Evn_T1_58 204 "干接点使用/未作温度采样使用" 205 "无效" ;
VAL_ 2332491642 SBMU_Evn_T2_58 204 "干接点使用/未作温度采样使用" 205 "无效" ;
VAL_ 2332491642 SBMU_Evn_T3_58 204 "干接点使用/未作温度采样使用" 205 "无效" ;
VAL_ 2332491642 S2A_STofCSCAutoCoding_58 0 "Initial" 1 "Successful" 2 "Failed" 3 "In Coding process" 4 "No Coding required" ;
VAL_ 2332491643 SBMU_Evn_T1_59 204 "干接点使用/未作温度采样使用" 205 "无效" ;
VAL_ 2332491643 SBMU_Evn_T2_59 204 "干接点使用/未作温度采样使用" 205 "无效" ;
VAL_ 2332491643 SBMU_Evn_T3_59 204 "干接点使用/未作温度采样使用" 205 "无效" ;
VAL_ 2332491643 S2A_STofCSCAutoCoding_59 0 "Initial" 1 "Successful" 2 "Failed" 3 "In Coding process" 4 "No Coding required" ;
VAL_ 2332491644 SBMU_Evn_T1_60 204 "干接点使用/未作温度采样使用" 205 "无效" ;
VAL_ 2332491644 SBMU_Evn_T2_60 204 "干接点使用/未作温度采样使用" 205 "无效" ;
VAL_ 2332491644 SBMU_Evn_T3_60 204 "干接点使用/未作温度采样使用" 205 "无效" ;
VAL_ 2332491644 S2A_STofCSCAutoCoding_60 0 "Initial" 1 "Successful" 2 "Failed" 3 "In Coding process" 4 "No Coding required" ;
VAL_ 2332491645 SBMU_Evn_T1_61 204 "干接点使用/未作温度采样使用" 205 "无效" ;
VAL_ 2332491645 SBMU_Evn_T2_61 204 "干接点使用/未作温度采样使用" 205 "无效" ;
VAL_ 2332491645 SBMU_Evn_T3_61 204 "干接点使用/未作温度采样使用" 205 "无效" ;
VAL_ 2332491645 S2A_STofCSCAutoCoding_61 0 "Initial" 1 "Successful" 2 "Failed" 3 "In Coding process" 4 "No Coding required" ;
VAL_ 2332491646 SBMU_Evn_T1_62 204 "干接点使用/未作温度采样使用" 205 "无效" ;
VAL_ 2332491646 SBMU_Evn_T2_62 204 "干接点使用/未作温度采样使用" 205 "无效" ;
VAL_ 2332491646 SBMU_Evn_T3_62 204 "干接点使用/未作温度采样使用" 205 "无效" ;
VAL_ 2332491646 S2A_STofCSCAutoCoding_62 0 "Initial" 1 "Successful" 2 "Failed" 3 "In Coding process" 4 "No Coding required" ;
VAL_ 2332491647 SBMU_Evn_T1_63 204 "干接点使用/未作温度采样使用" 205 "无效" ;
VAL_ 2332491647 SBMU_Evn_T2_63 204 "干接点使用/未作温度采样使用" 205 "无效" ;
VAL_ 2332491647 SBMU_Evn_T3_63 204 "干接点使用/未作温度采样使用" 205 "无效" ;
VAL_ 2332491647 S2A_STofCSCAutoCoding_63 0 "Initial" 1 "Successful" 2 "Failed" 3 "In Coding process" 4 "No Coding required" ;
VAL_ 2332557121 Status_of_Closed_Loop 0 "关闭" 1 "开启" ;
VAL_ 2332557121 S2A_S7_FullDisChgFlgFromSBMU_01 1 "置位满放," 0 "未置位满放" ;
VAL_ 2332557121 S2A_S7_Reserved_01 65535 "Invalid" ;
VAL_ 2332557121 S2A_S7_SOH_01 65535 "Invalid" ;
VAL_ 2332557122 Status_of_Closed_Loop 0 "关闭" 1 "开启" ;
VAL_ 2332557122 S2A_S7_FullDisChgFlgFromSBMU_02 1 "置位满放," 0 "未置位满放" ;
VAL_ 2332557122 S2A_S7_Reserved_02 65535 "Invalid" ;
VAL_ 2332557122 S2A_S7_SOH_02 65535 "Invalid" ;
VAL_ 2332557123 Status_of_Closed_Loop 0 "关闭" 1 "开启" ;
VAL_ 2332557123 S2A_S7_FullDisChgFlgFromSBMU_03 1 "置位满放," 0 "未置位满放" ;
VAL_ 2332557123 S2A_S7_Reserved_03 65535 "Invalid" ;
VAL_ 2332557123 S2A_S7_SOH_03 65535 "Invalid" ;
VAL_ 2332557124 Status_of_Closed_Loop 0 "关闭" 1 "开启" ;
VAL_ 2332557124 S2A_S7_FullDisChgFlgFromSBMU_04 1 "置位满放," 0 "未置位满放" ;
VAL_ 2332557124 S2A_S7_Reserved_04 65535 "Invalid" ;
VAL_ 2332557124 S2A_S7_SOH_04 65535 "Invalid" ;
VAL_ 2332557125 Status_of_Closed_Loop 0 "关闭" 1 "开启" ;
VAL_ 2332557125 S2A_S7_FullDisChgFlgFromSBMU_05 1 "置位满放," 0 "未置位满放" ;
VAL_ 2332557125 S2A_S7_Reserved_05 65535 "Invalid" ;
VAL_ 2332557125 S2A_S7_SOH_05 65535 "Invalid" ;
VAL_ 2332557126 Status_of_Closed_Loop 0 "关闭" 1 "开启" ;
VAL_ 2332557126 S2A_S7_FullDisChgFlgFromSBMU_06 1 "置位满放," 0 "未置位满放" ;
VAL_ 2332557126 S2A_S7_Reserved_06 65535 "Invalid" ;
VAL_ 2332557126 S2A_S7_SOH_06 65535 "Invalid" ;
VAL_ 2332557127 Status_of_Closed_Loop 0 "关闭" 1 "开启" ;
VAL_ 2332557127 S2A_S7_FullDisChgFlgFromSBMU_07 1 "置位满放," 0 "未置位满放" ;
VAL_ 2332557127 S2A_S7_Reserved_07 65535 "Invalid" ;
VAL_ 2332557127 S2A_S7_SOH_07 65535 "Invalid" ;
VAL_ 2332557128 Status_of_Closed_Loop 0 "关闭" 1 "开启" ;
VAL_ 2332557128 S2A_S7_FullDisChgFlgFromSBMU_08 1 "置位满放," 0 "未置位满放" ;
VAL_ 2332557128 S2A_S7_Reserved_08 65535 "Invalid" ;
VAL_ 2332557128 S2A_S7_SOH_08 65535 "Invalid" ;
VAL_ 2332557129 Status_of_Closed_Loop 0 "关闭" 1 "开启" ;
VAL_ 2332557129 S2A_S7_FullDisChgFlgFromSBMU_09 1 "置位满放," 0 "未置位满放" ;
VAL_ 2332557129 S2A_S7_Reserved_09 65535 "Invalid" ;
VAL_ 2332557129 S2A_S7_SOH_09 65535 "Invalid" ;
VAL_ 2332557130 Status_of_Closed_Loop 0 "关闭" 1 "开启" ;
VAL_ 2332557130 S2A_S7_FullDisChgFlgFromSBMU_10 1 "置位满放," 0 "未置位满放" ;
VAL_ 2332557130 S2A_S7_Reserved_10 65535 "Invalid" ;
VAL_ 2332557130 S2A_S7_SOH_10 65535 "Invalid" ;
VAL_ 2332557131 Status_of_Closed_Loop 0 "关闭" 1 "开启" ;
VAL_ 2332557131 S2A_S7_FullDisChgFlgFromSBMU_11 1 "置位满放," 0 "未置位满放" ;
VAL_ 2332557131 S2A_S7_Reserved_11 65535 "Invalid" ;
VAL_ 2332557131 S2A_S7_SOH_11 65535 "Invalid" ;
VAL_ 2332557132 Status_of_Closed_Loop 0 "关闭" 1 "开启" ;
VAL_ 2332557132 S2A_S7_FullDisChgFlgFromSBMU_12 1 "置位满放," 0 "未置位满放" ;
VAL_ 2332557132 S2A_S7_Reserved_12 65535 "Invalid" ;
VAL_ 2332557132 S2A_S7_SOH_12 65535 "Invalid" ;
VAL_ 2332557133 Status_of_Closed_Loop 0 "关闭" 1 "开启" ;
VAL_ 2332557133 S2A_S7_FullDisChgFlgFromSBMU_13 1 "置位满放," 0 "未置位满放" ;
VAL_ 2332557133 S2A_S7_Reserved_13 65535 "Invalid" ;
VAL_ 2332557133 S2A_S7_SOH_13 65535 "Invalid" ;
VAL_ 2332557134 Status_of_Closed_Loop 0 "关闭" 1 "开启" ;
VAL_ 2332557134 S2A_S7_FullDisChgFlgFromSBMU_14 1 "置位满放," 0 "未置位满放" ;
VAL_ 2332557134 S2A_S7_Reserved_14 65535 "Invalid" ;
VAL_ 2332557134 S2A_S7_SOH_14 65535 "Invalid" ;
VAL_ 2332557135 Status_of_Closed_Loop 0 "关闭" 1 "开启" ;
VAL_ 2332557135 S2A_S7_FullDisChgFlgFromSBMU_15 1 "置位满放," 0 "未置位满放" ;
VAL_ 2332557135 S2A_S7_Reserved_15 65535 "Invalid" ;
VAL_ 2332557135 S2A_S7_SOH_15 65535 "Invalid" ;
VAL_ 2332557136 Status_of_Closed_Loop 0 "关闭" 1 "开启" ;
VAL_ 2332557136 S2A_S7_FullDisChgFlgFromSBMU_16 1 "置位满放," 0 "未置位满放" ;
VAL_ 2332557136 S2A_S7_Reserved_16 65535 "Invalid" ;
VAL_ 2332557136 S2A_S7_SOH_16 65535 "Invalid" ;
VAL_ 2332557137 Status_of_Closed_Loop 0 "关闭" 1 "开启" ;
VAL_ 2332557137 S2A_S7_FullDisChgFlgFromSBMU_17 1 "置位满放," 0 "未置位满放" ;
VAL_ 2332557137 S2A_S7_Reserved_17 65535 "Invalid" ;
VAL_ 2332557137 S2A_S7_SOH_17 65535 "Invalid" ;
VAL_ 2332557138 Status_of_Closed_Loop 0 "关闭" 1 "开启" ;
VAL_ 2332557138 S2A_S7_FullDisChgFlgFromSBMU_18 1 "置位满放," 0 "未置位满放" ;
VAL_ 2332557138 S2A_S7_Reserved_18 65535 "Invalid" ;
VAL_ 2332557138 S2A_S7_SOH_18 65535 "Invalid" ;
VAL_ 2332557139 Status_of_Closed_Loop 0 "关闭" 1 "开启" ;
VAL_ 2332557139 S2A_S7_FullDisChgFlgFromSBMU_19 1 "置位满放," 0 "未置位满放" ;
VAL_ 2332557139 S2A_S7_Reserved_19 65535 "Invalid" ;
VAL_ 2332557139 S2A_S7_SOH_19 65535 "Invalid" ;
VAL_ 2332557140 Status_of_Closed_Loop 0 "关闭" 1 "开启" ;
VAL_ 2332557140 S2A_S7_FullDisChgFlgFromSBMU_20 1 "置位满放," 0 "未置位满放" ;
VAL_ 2332557140 S2A_S7_Reserved_20 65535 "Invalid" ;
VAL_ 2332557140 S2A_S7_SOH_20 65535 "Invalid" ;
VAL_ 2332557141 Status_of_Closed_Loop 0 "关闭" 1 "开启" ;
VAL_ 2332557141 S2A_S7_FullDisChgFlgFromSBMU_21 1 "置位满放," 0 "未置位满放" ;
VAL_ 2332557141 S2A_S7_Reserved_21 65535 "Invalid" ;
VAL_ 2332557141 S2A_S7_SOH_21 65535 "Invalid" ;
VAL_ 2332557142 Status_of_Closed_Loop 0 "关闭" 1 "开启" ;
VAL_ 2332557142 S2A_S7_FullDisChgFlgFromSBMU_22 1 "置位满放," 0 "未置位满放" ;
VAL_ 2332557142 S2A_S7_Reserved_22 65535 "Invalid" ;
VAL_ 2332557142 S2A_S7_SOH_22 65535 "Invalid" ;
VAL_ 2332557143 Status_of_Closed_Loop 0 "关闭" 1 "开启" ;
VAL_ 2332557143 S2A_S7_FullDisChgFlgFromSBMU_23 1 "置位满放," 0 "未置位满放" ;
VAL_ 2332557143 S2A_S7_Reserved_23 65535 "Invalid" ;
VAL_ 2332557143 S2A_S7_SOH_23 65535 "Invalid" ;
VAL_ 2332557144 Status_of_Closed_Loop 0 "关闭" 1 "开启" ;
VAL_ 2332557144 S2A_S7_FullDisChgFlgFromSBMU_24 1 "置位满放," 0 "未置位满放" ;
VAL_ 2332557144 S2A_S7_Reserved_24 65535 "Invalid" ;
VAL_ 2332557144 S2A_S7_SOH_24 65535 "Invalid" ;
VAL_ 2332557145 Status_of_Closed_Loop 0 "关闭" 1 "开启" ;
VAL_ 2332557145 S2A_S7_FullDisChgFlgFromSBMU_25 1 "置位满放," 0 "未置位满放" ;
VAL_ 2332557145 S2A_S7_Reserved_25 65535 "Invalid" ;
VAL_ 2332557145 S2A_S7_SOH_25 65535 "Invalid" ;
VAL_ 2332557146 Status_of_Closed_Loop 0 "关闭" 1 "开启" ;
VAL_ 2332557146 S2A_S7_FullDisChgFlgFromSBMU_26 1 "置位满放," 0 "未置位满放" ;
VAL_ 2332557146 S2A_S7_Reserved_26 65535 "Invalid" ;
VAL_ 2332557146 S2A_S7_SOH_26 65535 "Invalid" ;
VAL_ 2332557147 Status_of_Closed_Loop 0 "关闭" 1 "开启" ;
VAL_ 2332557147 S2A_S7_FullDisChgFlgFromSBMU_27 1 "置位满放," 0 "未置位满放" ;
VAL_ 2332557147 S2A_S7_Reserved_27 65535 "Invalid" ;
VAL_ 2332557147 S2A_S7_SOH_27 65535 "Invalid" ;
VAL_ 2332557148 Status_of_Closed_Loop 0 "关闭" 1 "开启" ;
VAL_ 2332557148 S2A_S7_FullDisChgFlgFromSBMU_28 1 "置位满放," 0 "未置位满放" ;
VAL_ 2332557148 S2A_S7_Reserved_28 65535 "Invalid" ;
VAL_ 2332557148 S2A_S7_SOH_28 65535 "Invalid" ;
VAL_ 2332557149 Status_of_Closed_Loop 0 "关闭" 1 "开启" ;
VAL_ 2332557149 S2A_S7_FullDisChgFlgFromSBMU_29 1 "置位满放," 0 "未置位满放" ;
VAL_ 2332557149 S2A_S7_Reserved_29 65535 "Invalid" ;
VAL_ 2332557149 S2A_S7_SOH_29 65535 "Invalid" ;
VAL_ 2332557150 Status_of_Closed_Loop 0 "关闭" 1 "开启" ;
VAL_ 2332557150 S2A_S7_FullDisChgFlgFromSBMU_30 1 "置位满放," 0 "未置位满放" ;
VAL_ 2332557150 S2A_S7_Reserved_30 65535 "Invalid" ;
VAL_ 2332557150 S2A_S7_SOH_30 65535 "Invalid" ;
VAL_ 2332557151 Status_of_Closed_Loop 0 "关闭" 1 "开启" ;
VAL_ 2332557151 S2A_S7_FullDisChgFlgFromSBMU_31 1 "置位满放," 0 "未置位满放" ;
VAL_ 2332557151 S2A_S7_Reserved_31 65535 "Invalid" ;
VAL_ 2332557151 S2A_S7_SOH_31 65535 "Invalid" ;
VAL_ 2332557152 Status_of_Closed_Loop 0 "关闭" 1 "开启" ;
VAL_ 2332557152 S2A_S7_FullDisChgFlgFromSBMU_32 1 "置位满放," 0 "未置位满放" ;
VAL_ 2332557152 S2A_S7_Reserved_32 65535 "Invalid" ;
VAL_ 2332557152 S2A_S7_SOH_32 65535 "Invalid" ;
VERSION ""

NS_ :

BS_:

BU_: MBMU PC SBMU IMM ETH DCDC LEMS

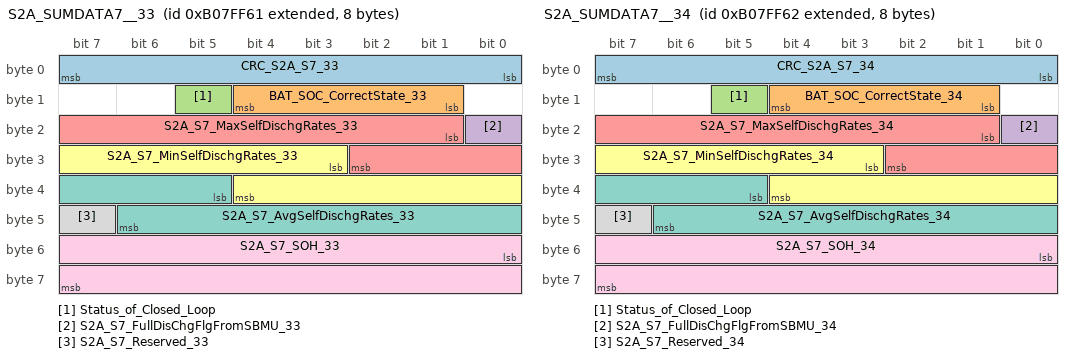
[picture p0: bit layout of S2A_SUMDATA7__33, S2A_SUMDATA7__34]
BO_ 2332557153 S2A_SUMDATA7__33: 8 SBMU
 SG_ CRC_S2A_S7_33 : 0|8@1+ (1,0) [0|255] ""  MBMU
 SG_ BAT_SOC_CorrectState_33 : 9|4@1+ (1,0) [0|15] ""  MBMU
 SG_ Status_of_Closed_Loop : 13|1@1+ (1,0) [0|1] ""  MBMU
 SG_ S2A_S7_FullDisChgFlgFromSBMU_33 : 16|1@1+ (1,0) [0|1] ""  MBMU
 SG_ S2A_S7_MaxSelfDischgRates_33 : 17|10@1+ (0.1,0) [0|102.3] "%"  MBMU,PC
 SG_ S2A_S7_MinSelfDischgRates_33 : 27|10@1+ (0.1,0) [0|102.3] "%"  MBMU,PC
 SG_ S2A_S7_AvgSelfDischgRates_33 : 37|10@1+ (0.1,0) [0|102.3] "%"  MBMU,PC
 SG_ S2A_S7_Reserved_33 : 47|1@1+ (1,0) [0|1] ""  MBMU
 SG_ S2A_S7_SOH_33 : 48|16@1+ (0.1,0) [0|6553.5] ""  MBMU

BO_ 2332557154 S2A_SUMDATA7__34: 8 SBMU
 SG_ CRC_S2A_S7_34 : 0|8@1+ (1,0) [0|255] ""  MBMU
 SG_ BAT_SOC_CorrectState_34 : 9|4@1+ (1,0) [0|15] ""  MBMU
 SG_ Status_of_Closed_Loop : 13|1@1+ (1,0) [0|1] ""  MBMU
 SG_ S2A_S7_FullDisChgFlgFromSBMU_34 : 16|1@1+ (1,0) [0|1] ""  MBMU
 SG_ S2A_S7_MaxSelfDischgRates_34 : 17|10@1+ (0.1,0) [0|102.3] "%"  MBMU,PC
 SG_ S2A_S7_MinSelfDischgRates_34 : 27|10@1+ (0.1,0) [0|102.3] "%"  MBMU,PC
 SG_ S2A_S7_AvgSelfDischgRates_34 : 37|10@1+ (0.1,0) [0|102.3] "%"  MBMU,PC
 SG_ S2A_S7_Reserved_34 : 47|1@1+ (1,0) [0|1] ""  MBMU
 SG_ S2A_S7_SOH_34 : 48|16@1+ (0.1,0) [0|6553.5] ""  MBMU

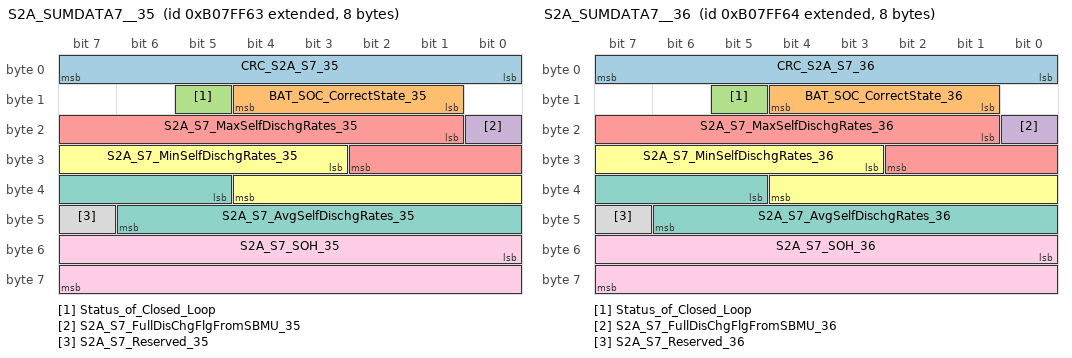
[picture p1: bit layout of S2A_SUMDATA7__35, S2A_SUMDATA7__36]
BO_ 2332557155 S2A_SUMDATA7__35: 8 SBMU
 SG_ CRC_S2A_S7_35 : 0|8@1+ (1,0) [0|255] ""  MBMU
 SG_ BAT_SOC_CorrectState_35 : 9|4@1+ (1,0) [0|15] ""  MBMU
 SG_ Status_of_Closed_Loop : 13|1@1+ (1,0) [0|1] ""  MBMU
 SG_ S2A_S7_FullDisChgFlgFromSBMU_35 : 16|1@1+ (1,0) [0|1] ""  MBMU
 SG_ S2A_S7_MaxSelfDischgRates_35 : 17|10@1+ (0.1,0) [0|102.3] "%"  MBMU,PC
 SG_ S2A_S7_MinSelfDischgRates_35 : 27|10@1+ (0.1,0) [0|102.3] "%"  MBMU,PC
 SG_ S2A_S7_AvgSelfDischgRates_35 : 37|10@1+ (0.1,0) [0|102.3] "%"  MBMU,PC
 SG_ S2A_S7_Reserved_35 : 47|1@1+ (1,0) [0|1] ""  MBMU
 SG_ S2A_S7_SOH_35 : 48|16@1+ (0.1,0) [0|6553.5] ""  MBMU

BO_ 2332557156 S2A_SUMDATA7__36: 8 SBMU
 SG_ CRC_S2A_S7_36 : 0|8@1+ (1,0) [0|255] ""  MBMU
 SG_ BAT_SOC_CorrectState_36 : 9|4@1+ (1,0) [0|15] ""  MBMU
 SG_ Status_of_Closed_Loop : 13|1@1+ (1,0) [0|1] ""  MBMU
 SG_ S2A_S7_FullDisChgFlgFromSBMU_36 : 16|1@1+ (1,0) [0|1] ""  MBMU
 SG_ S2A_S7_MaxSelfDischgRates_36 : 17|10@1+ (0.1,0) [0|102.3] "%"  MBMU,PC
 SG_ S2A_S7_MinSelfDischgRates_36 : 27|10@1+ (0.1,0) [0|102.3] "%"  MBMU,PC
 SG_ S2A_S7_AvgSelfDischgRates_36 : 37|10@1+ (0.1,0) [0|102.3] "%"  MBMU,PC
 SG_ S2A_S7_Reserved_36 : 47|1@1+ (1,0) [0|1] ""  MBMU
 SG_ S2A_S7_SOH_36 : 48|16@1+ (0.1,0) [0|6553.5] ""  MBMU

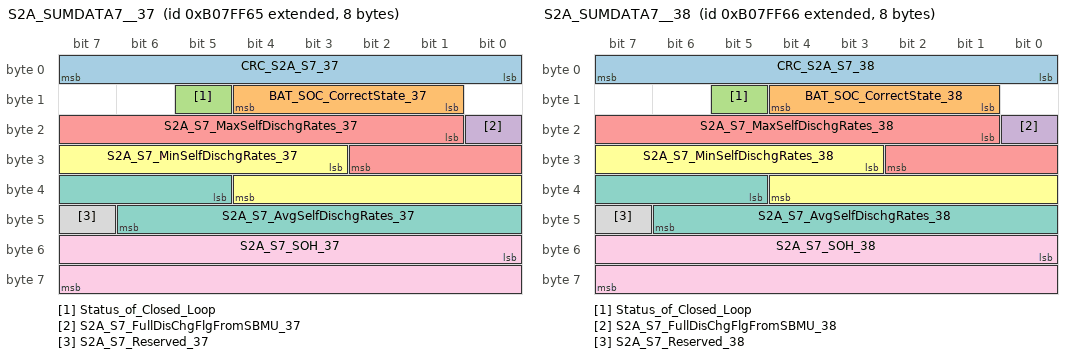
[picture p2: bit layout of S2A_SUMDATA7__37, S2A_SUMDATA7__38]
BO_ 2332557157 S2A_SUMDATA7__37: 8 SBMU
 SG_ CRC_S2A_S7_37 : 0|8@1+ (1,0) [0|255] ""  MBMU
 SG_ BAT_SOC_CorrectState_37 : 9|4@1+ (1,0) [0|15] ""  MBMU
 SG_ Status_of_Closed_Loop : 13|1@1+ (1,0) [0|1] ""  MBMU
 SG_ S2A_S7_FullDisChgFlgFromSBMU_37 : 16|1@1+ (1,0) [0|1] ""  MBMU
 SG_ S2A_S7_MaxSelfDischgRates_37 : 17|10@1+ (0.1,0) [0|102.3] "%"  MBMU,PC
 SG_ S2A_S7_MinSelfDischgRates_37 : 27|10@1+ (0.1,0) [0|102.3] "%"  MBMU,PC
 SG_ S2A_S7_AvgSelfDischgRates_37 : 37|10@1+ (0.1,0) [0|102.3] "%"  MBMU,PC
 SG_ S2A_S7_Reserved_37 : 47|1@1+ (1,0) [0|1] ""  MBMU
 SG_ S2A_S7_SOH_37 : 48|16@1+ (0.1,0) [0|6553.5] ""  MBMU

BO_ 2332557158 S2A_SUMDATA7__38: 8 SBMU
 SG_ CRC_S2A_S7_38 : 0|8@1+ (1,0) [0|255] ""  MBMU
 SG_ BAT_SOC_CorrectState_38 : 9|4@1+ (1,0) [0|15] ""  MBMU
 SG_ Status_of_Closed_Loop : 13|1@1+ (1,0) [0|1] ""  MBMU
 SG_ S2A_S7_FullDisChgFlgFromSBMU_38 : 16|1@1+ (1,0) [0|1] ""  MBMU
 SG_ S2A_S7_MaxSelfDischgRates_38 : 17|10@1+ (0.1,0) [0|102.3] "%"  MBMU,PC
 SG_ S2A_S7_MinSelfDischgRates_38 : 27|10@1+ (0.1,0) [0|102.3] "%"  MBMU,PC
 SG_ S2A_S7_AvgSelfDischgRates_38 : 37|10@1+ (0.1,0) [0|102.3] "%"  MBMU,PC
 SG_ S2A_S7_Reserved_38 : 47|1@1+ (1,0) [0|1] ""  MBMU
 SG_ S2A_S7_SOH_38 : 48|16@1+ (0.1,0) [0|6553.5] ""  MBMU

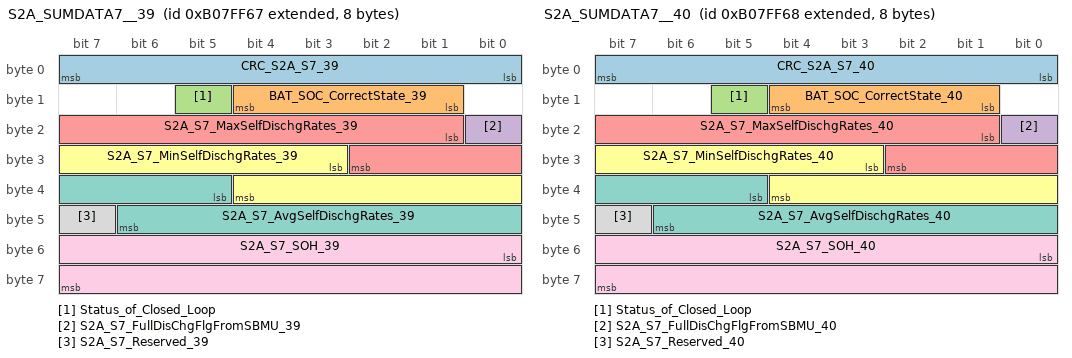
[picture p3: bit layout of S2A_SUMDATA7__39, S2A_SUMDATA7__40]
BO_ 2332557159 S2A_SUMDATA7__39: 8 SBMU
 SG_ CRC_S2A_S7_39 : 0|8@1+ (1,0) [0|255] ""  MBMU
 SG_ BAT_SOC_CorrectState_39 : 9|4@1+ (1,0) [0|15] ""  MBMU
 SG_ Status_of_Closed_Loop : 13|1@1+ (1,0) [0|1] ""  MBMU
 SG_ S2A_S7_FullDisChgFlgFromSBMU_39 : 16|1@1+ (1,0) [0|1] ""  MBMU
 SG_ S2A_S7_MaxSelfDischgRates_39 : 17|10@1+ (0.1,0) [0|102.3] "%"  MBMU,PC
 SG_ S2A_S7_MinSelfDischgRates_39 : 27|10@1+ (0.1,0) [0|102.3] "%"  MBMU,PC
 SG_ S2A_S7_AvgSelfDischgRates_39 : 37|10@1+ (0.1,0) [0|102.3] "%"  MBMU,PC
 SG_ S2A_S7_Reserved_39 : 47|1@1+ (1,0) [0|1] ""  MBMU
 SG_ S2A_S7_SOH_39 : 48|16@1+ (0.1,0) [0|6553.5] ""  MBMU

BO_ 2332557160 S2A_SUMDATA7__40: 8 SBMU
 SG_ CRC_S2A_S7_40 : 0|8@1+ (1,0) [0|255] ""  MBMU
 SG_ BAT_SOC_CorrectState_40 : 9|4@1+ (1,0) [0|15] ""  MBMU
 SG_ Status_of_Closed_Loop : 13|1@1+ (1,0) [0|1] ""  MBMU
 SG_ S2A_S7_FullDisChgFlgFromSBMU_40 : 16|1@1+ (1,0) [0|1] ""  MBMU
 SG_ S2A_S7_MaxSelfDischgRates_40 : 17|10@1+ (0.1,0) [0|102.3] "%"  MBMU,PC
 SG_ S2A_S7_MinSelfDischgRates_40 : 27|10@1+ (0.1,0) [0|102.3] "%"  MBMU,PC
 SG_ S2A_S7_AvgSelfDischgRates_40 : 37|10@1+ (0.1,0) [0|102.3] "%"  MBMU,PC
 SG_ S2A_S7_Reserved_40 : 47|1@1+ (1,0) [0|1] ""  MBMU
 SG_ S2A_S7_SOH_40 : 48|16@1+ (0.1,0) [0|6553.5] ""  MBMU

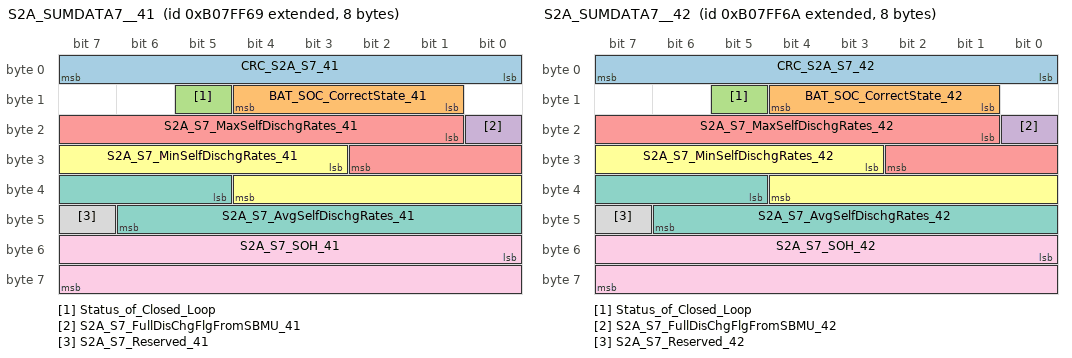
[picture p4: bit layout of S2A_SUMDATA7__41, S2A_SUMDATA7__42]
BO_ 2332557161 S2A_SUMDATA7__41: 8 SBMU
 SG_ CRC_S2A_S7_41 : 0|8@1+ (1,0) [0|255] ""  MBMU
 SG_ BAT_SOC_CorrectState_41 : 9|4@1+ (1,0) [0|15] ""  MBMU
 SG_ Status_of_Closed_Loop : 13|1@1+ (1,0) [0|1] ""  MBMU
 SG_ S2A_S7_FullDisChgFlgFromSBMU_41 : 16|1@1+ (1,0) [0|1] ""  MBMU
 SG_ S2A_S7_MaxSelfDischgRates_41 : 17|10@1+ (0.1,0) [0|102.3] "%"  MBMU,PC
 SG_ S2A_S7_MinSelfDischgRates_41 : 27|10@1+ (0.1,0) [0|102.3] "%"  MBMU,PC
 SG_ S2A_S7_AvgSelfDischgRates_41 : 37|10@1+ (0.1,0) [0|102.3] "%"  MBMU,PC
 SG_ S2A_S7_Reserved_41 : 47|1@1+ (1,0) [0|1] ""  MBMU
 SG_ S2A_S7_SOH_41 : 48|16@1+ (0.1,0) [0|6553.5] ""  MBMU

BO_ 2332557162 S2A_SUMDATA7__42: 8 SBMU
 SG_ CRC_S2A_S7_42 : 0|8@1+ (1,0) [0|255] ""  MBMU
 SG_ BAT_SOC_CorrectState_42 : 9|4@1+ (1,0) [0|15] ""  MBMU
 SG_ Status_of_Closed_Loop : 13|1@1+ (1,0) [0|1] ""  MBMU
 SG_ S2A_S7_FullDisChgFlgFromSBMU_42 : 16|1@1+ (1,0) [0|1] ""  MBMU
 SG_ S2A_S7_MaxSelfDischgRates_42 : 17|10@1+ (0.1,0) [0|102.3] "%"  MBMU,PC
 SG_ S2A_S7_MinSelfDischgRates_42 : 27|10@1+ (0.1,0) [0|102.3] "%"  MBMU,PC
 SG_ S2A_S7_AvgSelfDischgRates_42 : 37|10@1+ (0.1,0) [0|102.3] "%"  MBMU,PC
 SG_ S2A_S7_Reserved_42 : 47|1@1+ (1,0) [0|1] ""  MBMU
 SG_ S2A_S7_SOH_42 : 48|16@1+ (0.1,0) [0|6553.5] ""  MBMU

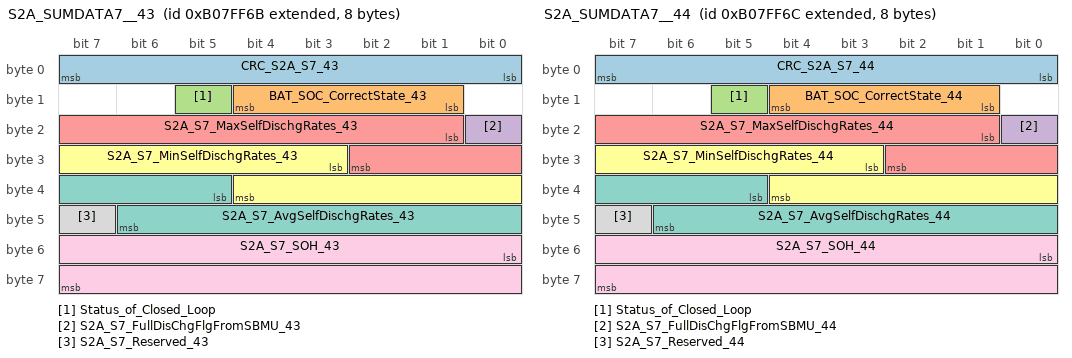
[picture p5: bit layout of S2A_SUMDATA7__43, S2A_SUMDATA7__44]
BO_ 2332557163 S2A_SUMDATA7__43: 8 SBMU
 SG_ CRC_S2A_S7_43 : 0|8@1+ (1,0) [0|255] ""  MBMU
 SG_ BAT_SOC_CorrectState_43 : 9|4@1+ (1,0) [0|15] ""  MBMU
 SG_ Status_of_Closed_Loop : 13|1@1+ (1,0) [0|1] ""  MBMU
 SG_ S2A_S7_FullDisChgFlgFromSBMU_43 : 16|1@1+ (1,0) [0|1] ""  MBMU
 SG_ S2A_S7_MaxSelfDischgRates_43 : 17|10@1+ (0.1,0) [0|102.3] "%"  MBMU,PC
 SG_ S2A_S7_MinSelfDischgRates_43 : 27|10@1+ (0.1,0) [0|102.3] "%"  MBMU,PC
 SG_ S2A_S7_AvgSelfDischgRates_43 : 37|10@1+ (0.1,0) [0|102.3] "%"  MBMU,PC
 SG_ S2A_S7_Reserved_43 : 47|1@1+ (1,0) [0|1] ""  MBMU
 SG_ S2A_S7_SOH_43 : 48|16@1+ (0.1,0) [0|6553.5] ""  MBMU

BO_ 2332557164 S2A_SUMDATA7__44: 8 SBMU
 SG_ CRC_S2A_S7_44 : 0|8@1+ (1,0) [0|255] ""  MBMU
 SG_ BAT_SOC_CorrectState_44 : 9|4@1+ (1,0) [0|15] ""  MBMU
 SG_ Status_of_Closed_Loop : 13|1@1+ (1,0) [0|1] ""  MBMU
 SG_ S2A_S7_FullDisChgFlgFromSBMU_44 : 16|1@1+ (1,0) [0|1] ""  MBMU
 SG_ S2A_S7_MaxSelfDischgRates_44 : 17|10@1+ (0.1,0) [0|102.3] "%"  MBMU,PC
 SG_ S2A_S7_MinSelfDischgRates_44 : 27|10@1+ (0.1,0) [0|102.3] "%"  MBMU,PC
 SG_ S2A_S7_AvgSelfDischgRates_44 : 37|10@1+ (0.1,0) [0|102.3] "%"  MBMU,PC
 SG_ S2A_S7_Reserved_44 : 47|1@1+ (1,0) [0|1] ""  MBMU
 SG_ S2A_S7_SOH_44 : 48|16@1+ (0.1,0) [0|6553.5] ""  MBMU

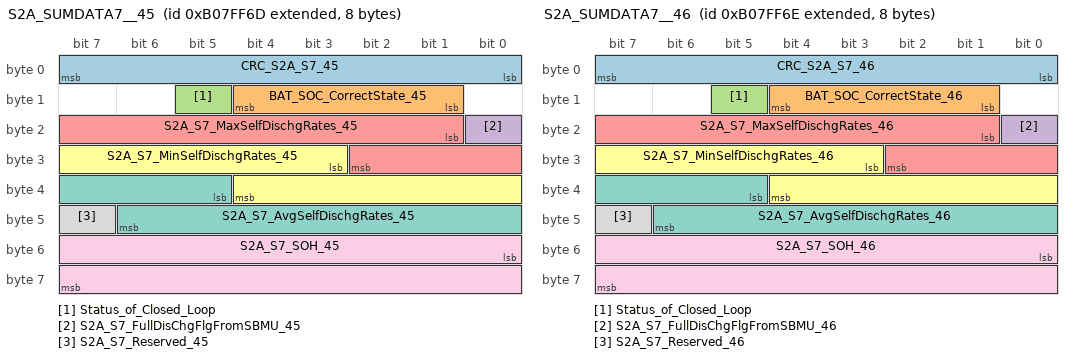
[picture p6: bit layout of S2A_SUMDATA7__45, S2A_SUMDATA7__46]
BO_ 2332557165 S2A_SUMDATA7__45: 8 SBMU
 SG_ CRC_S2A_S7_45 : 0|8@1+ (1,0) [0|255] ""  MBMU
 SG_ BAT_SOC_CorrectState_45 : 9|4@1+ (1,0) [0|15] ""  MBMU
 SG_ Status_of_Closed_Loop : 13|1@1+ (1,0) [0|1] ""  MBMU
 SG_ S2A_S7_FullDisChgFlgFromSBMU_45 : 16|1@1+ (1,0) [0|1] ""  MBMU
 SG_ S2A_S7_MaxSelfDischgRates_45 : 17|10@1+ (0.1,0) [0|102.3] "%"  MBMU,PC
 SG_ S2A_S7_MinSelfDischgRates_45 : 27|10@1+ (0.1,0) [0|102.3] "%"  MBMU,PC
 SG_ S2A_S7_AvgSelfDischgRates_45 : 37|10@1+ (0.1,0) [0|102.3] "%"  MBMU,PC
 SG_ S2A_S7_Reserved_45 : 47|1@1+ (1,0) [0|1] ""  MBMU
 SG_ S2A_S7_SOH_45 : 48|16@1+ (0.1,0) [0|6553.5] ""  MBMU

BO_ 2332557166 S2A_SUMDATA7__46: 8 SBMU
 SG_ CRC_S2A_S7_46 : 0|8@1+ (1,0) [0|255] ""  MBMU
 SG_ BAT_SOC_CorrectState_46 : 9|4@1+ (1,0) [0|15] ""  MBMU
 SG_ Status_of_Closed_Loop : 13|1@1+ (1,0) [0|1] ""  MBMU
 SG_ S2A_S7_FullDisChgFlgFromSBMU_46 : 16|1@1+ (1,0) [0|1] ""  MBMU
 SG_ S2A_S7_MaxSelfDischgRates_46 : 17|10@1+ (0.1,0) [0|102.3] "%"  MBMU,PC
 SG_ S2A_S7_MinSelfDischgRates_46 : 27|10@1+ (0.1,0) [0|102.3] "%"  MBMU,PC
 SG_ S2A_S7_AvgSelfDischgRates_46 : 37|10@1+ (0.1,0) [0|102.3] "%"  MBMU,PC
 SG_ S2A_S7_Reserved_46 : 47|1@1+ (1,0) [0|1] ""  MBMU
 SG_ S2A_S7_SOH_46 : 48|16@1+ (0.1,0) [0|6553.5] ""  MBMU

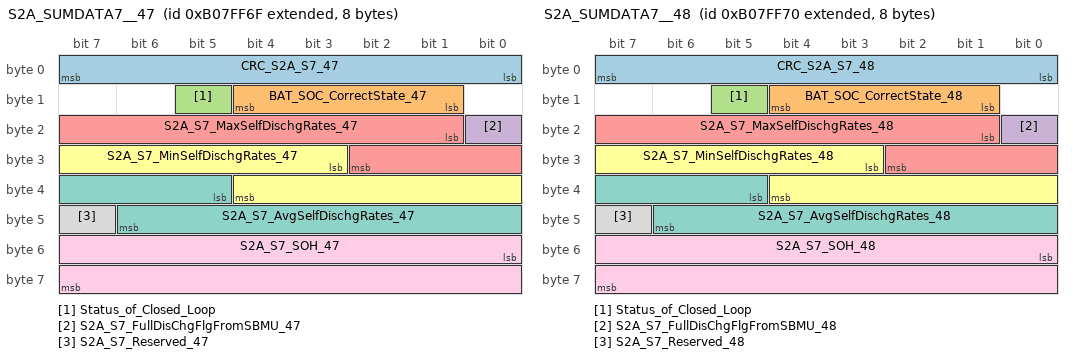
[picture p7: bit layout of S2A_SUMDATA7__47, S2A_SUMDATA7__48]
BO_ 2332557167 S2A_SUMDATA7__47: 8 SBMU
 SG_ CRC_S2A_S7_47 : 0|8@1+ (1,0) [0|255] ""  MBMU
 SG_ BAT_SOC_CorrectState_47 : 9|4@1+ (1,0) [0|15] ""  MBMU
 SG_ Status_of_Closed_Loop : 13|1@1+ (1,0) [0|1] ""  MBMU
 SG_ S2A_S7_FullDisChgFlgFromSBMU_47 : 16|1@1+ (1,0) [0|1] ""  MBMU
 SG_ S2A_S7_MaxSelfDischgRates_47 : 17|10@1+ (0.1,0) [0|102.3] "%"  MBMU,PC
 SG_ S2A_S7_MinSelfDischgRates_47 : 27|10@1+ (0.1,0) [0|102.3] "%"  MBMU,PC
 SG_ S2A_S7_AvgSelfDischgRates_47 : 37|10@1+ (0.1,0) [0|102.3] "%"  MBMU,PC
 SG_ S2A_S7_Reserved_47 : 47|1@1+ (1,0) [0|1] ""  MBMU
 SG_ S2A_S7_SOH_47 : 48|16@1+ (0.1,0) [0|6553.5] ""  MBMU

BO_ 2332557168 S2A_SUMDATA7__48: 8 SBMU
 SG_ CRC_S2A_S7_48 : 0|8@1+ (1,0) [0|255] ""  MBMU
 SG_ BAT_SOC_CorrectState_48 : 9|4@1+ (1,0) [0|15] ""  MBMU
 SG_ Status_of_Closed_Loop : 13|1@1+ (1,0) [0|1] ""  MBMU
 SG_ S2A_S7_FullDisChgFlgFromSBMU_48 : 16|1@1+ (1,0) [0|1] ""  MBMU
 SG_ S2A_S7_MaxSelfDischgRates_48 : 17|10@1+ (0.1,0) [0|102.3] "%"  MBMU,PC
 SG_ S2A_S7_MinSelfDischgRates_48 : 27|10@1+ (0.1,0) [0|102.3] "%"  MBMU,PC
 SG_ S2A_S7_AvgSelfDischgRates_48 : 37|10@1+ (0.1,0) [0|102.3] "%"  MBMU,PC
 SG_ S2A_S7_Reserved_48 : 47|1@1+ (1,0) [0|1] ""  MBMU
 SG_ S2A_S7_SOH_48 : 48|16@1+ (0.1,0) [0|6553.5] ""  MBMU

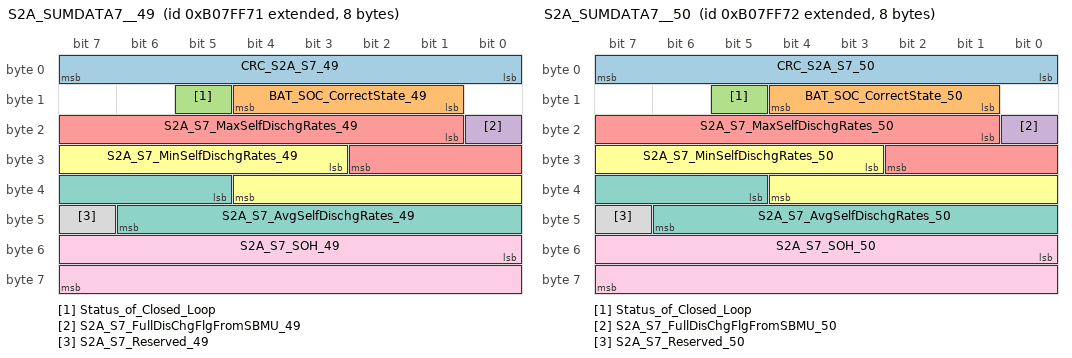
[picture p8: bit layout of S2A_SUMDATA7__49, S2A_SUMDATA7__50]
BO_ 2332557169 S2A_SUMDATA7__49: 8 SBMU
 SG_ CRC_S2A_S7_49 : 0|8@1+ (1,0) [0|255] ""  MBMU
 SG_ BAT_SOC_CorrectState_49 : 9|4@1+ (1,0) [0|15] ""  MBMU
 SG_ Status_of_Closed_Loop : 13|1@1+ (1,0) [0|1] ""  MBMU
 SG_ S2A_S7_FullDisChgFlgFromSBMU_49 : 16|1@1+ (1,0) [0|1] ""  MBMU
 SG_ S2A_S7_MaxSelfDischgRates_49 : 17|10@1+ (0.1,0) [0|102.3] "%"  MBMU,PC
 SG_ S2A_S7_MinSelfDischgRates_49 : 27|10@1+ (0.1,0) [0|102.3] "%"  MBMU,PC
 SG_ S2A_S7_AvgSelfDischgRates_49 : 37|10@1+ (0.1,0) [0|102.3] "%"  MBMU,PC
 SG_ S2A_S7_Reserved_49 : 47|1@1+ (1,0) [0|1] ""  MBMU
 SG_ S2A_S7_SOH_49 : 48|16@1+ (0.1,0) [0|6553.5] ""  MBMU

BO_ 2332557170 S2A_SUMDATA7__50: 8 SBMU
 SG_ CRC_S2A_S7_50 : 0|8@1+ (1,0) [0|255] ""  MBMU
 SG_ BAT_SOC_CorrectState_50 : 9|4@1+ (1,0) [0|15] ""  MBMU
 SG_ Status_of_Closed_Loop : 13|1@1+ (1,0) [0|1] ""  MBMU
 SG_ S2A_S7_FullDisChgFlgFromSBMU_50 : 16|1@1+ (1,0) [0|1] ""  MBMU
 SG_ S2A_S7_MaxSelfDischgRates_50 : 17|10@1+ (0.1,0) [0|102.3] "%"  MBMU,PC
 SG_ S2A_S7_MinSelfDischgRates_50 : 27|10@1+ (0.1,0) [0|102.3] "%"  MBMU,PC
 SG_ S2A_S7_AvgSelfDischgRates_50 : 37|10@1+ (0.1,0) [0|102.3] "%"  MBMU,PC
 SG_ S2A_S7_Reserved_50 : 47|1@1+ (1,0) [0|1] ""  MBMU
 SG_ S2A_S7_SOH_50 : 48|16@1+ (0.1,0) [0|6553.5] ""  MBMU

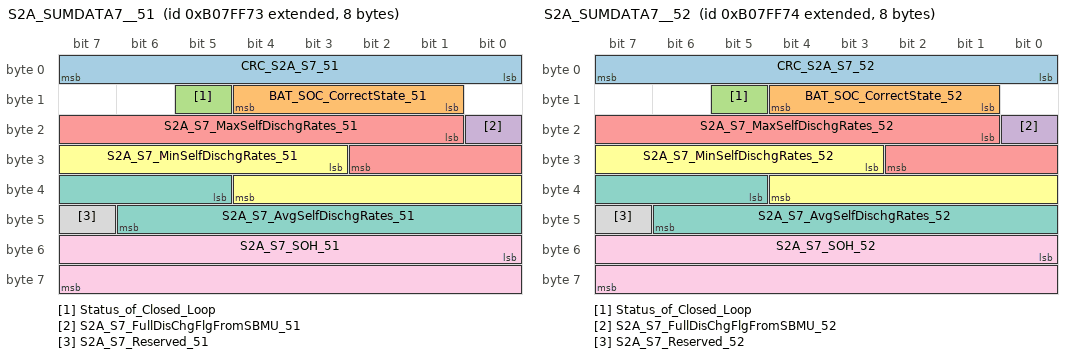
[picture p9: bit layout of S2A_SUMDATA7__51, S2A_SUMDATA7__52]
BO_ 2332557171 S2A_SUMDATA7__51: 8 SBMU
 SG_ CRC_S2A_S7_51 : 0|8@1+ (1,0) [0|255] ""  MBMU
 SG_ BAT_SOC_CorrectState_51 : 9|4@1+ (1,0) [0|15] ""  MBMU
 SG_ Status_of_Closed_Loop : 13|1@1+ (1,0) [0|1] ""  MBMU
 SG_ S2A_S7_FullDisChgFlgFromSBMU_51 : 16|1@1+ (1,0) [0|1] ""  MBMU
 SG_ S2A_S7_MaxSelfDischgRates_51 : 17|10@1+ (0.1,0) [0|102.3] "%"  MBMU,PC
 SG_ S2A_S7_MinSelfDischgRates_51 : 27|10@1+ (0.1,0) [0|102.3] "%"  MBMU,PC
 SG_ S2A_S7_AvgSelfDischgRates_51 : 37|10@1+ (0.1,0) [0|102.3] "%"  MBMU,PC
 SG_ S2A_S7_Reserved_51 : 47|1@1+ (1,0) [0|1] ""  MBMU
 SG_ S2A_S7_SOH_51 : 48|16@1+ (0.1,0) [0|6553.5] ""  MBMU

BO_ 2332557172 S2A_SUMDATA7__52: 8 SBMU
 SG_ CRC_S2A_S7_52 : 0|8@1+ (1,0) [0|255] ""  MBMU
 SG_ BAT_SOC_CorrectState_52 : 9|4@1+ (1,0) [0|15] ""  MBMU
 SG_ Status_of_Closed_Loop : 13|1@1+ (1,0) [0|1] ""  MBMU
 SG_ S2A_S7_FullDisChgFlgFromSBMU_52 : 16|1@1+ (1,0) [0|1] ""  MBMU
 SG_ S2A_S7_MaxSelfDischgRates_52 : 17|10@1+ (0.1,0) [0|102.3] "%"  MBMU,PC
 SG_ S2A_S7_MinSelfDischgRates_52 : 27|10@1+ (0.1,0) [0|102.3] "%"  MBMU,PC
 SG_ S2A_S7_AvgSelfDischgRates_52 : 37|10@1+ (0.1,0) [0|102.3] "%"  MBMU,PC
 SG_ S2A_S7_Reserved_52 : 47|1@1+ (1,0) [0|1] ""  MBMU
 SG_ S2A_S7_SOH_52 : 48|16@1+ (0.1,0) [0|6553.5] ""  MBMU

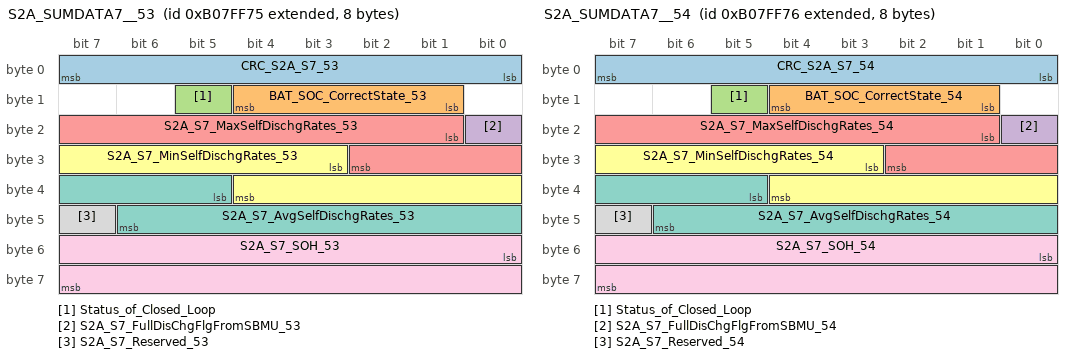
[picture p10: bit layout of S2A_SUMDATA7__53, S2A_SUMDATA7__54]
BO_ 2332557173 S2A_SUMDATA7__53: 8 SBMU
 SG_ CRC_S2A_S7_53 : 0|8@1+ (1,0) [0|255] ""  MBMU
 SG_ BAT_SOC_CorrectState_53 : 9|4@1+ (1,0) [0|15] ""  MBMU
 SG_ Status_of_Closed_Loop : 13|1@1+ (1,0) [0|1] ""  MBMU
 SG_ S2A_S7_FullDisChgFlgFromSBMU_53 : 16|1@1+ (1,0) [0|1] ""  MBMU
 SG_ S2A_S7_MaxSelfDischgRates_53 : 17|10@1+ (0.1,0) [0|102.3] "%"  MBMU,PC
 SG_ S2A_S7_MinSelfDischgRates_53 : 27|10@1+ (0.1,0) [0|102.3] "%"  MBMU,PC
 SG_ S2A_S7_AvgSelfDischgRates_53 : 37|10@1+ (0.1,0) [0|102.3] "%"  MBMU,PC
 SG_ S2A_S7_Reserved_53 : 47|1@1+ (1,0) [0|1] ""  MBMU
 SG_ S2A_S7_SOH_53 : 48|16@1+ (0.1,0) [0|6553.5] ""  MBMU

BO_ 2332557174 S2A_SUMDATA7__54: 8 SBMU
 SG_ CRC_S2A_S7_54 : 0|8@1+ (1,0) [0|255] ""  MBMU
 SG_ BAT_SOC_CorrectState_54 : 9|4@1+ (1,0) [0|15] ""  MBMU
 SG_ Status_of_Closed_Loop : 13|1@1+ (1,0) [0|1] ""  MBMU
 SG_ S2A_S7_FullDisChgFlgFromSBMU_54 : 16|1@1+ (1,0) [0|1] ""  MBMU
 SG_ S2A_S7_MaxSelfDischgRates_54 : 17|10@1+ (0.1,0) [0|102.3] "%"  MBMU,PC
 SG_ S2A_S7_MinSelfDischgRates_54 : 27|10@1+ (0.1,0) [0|102.3] "%"  MBMU,PC
 SG_ S2A_S7_AvgSelfDischgRates_54 : 37|10@1+ (0.1,0) [0|102.3] "%"  MBMU,PC
 SG_ S2A_S7_Reserved_54 : 47|1@1+ (1,0) [0|1] ""  MBMU
 SG_ S2A_S7_SOH_54 : 48|16@1+ (0.1,0) [0|6553.5] ""  MBMU

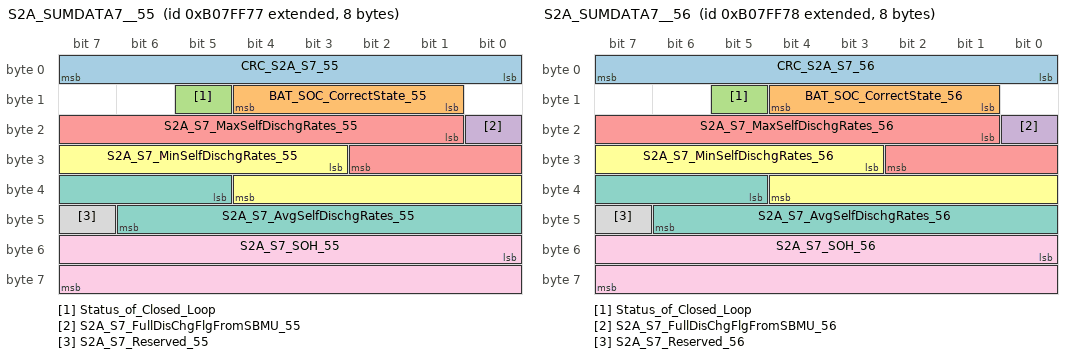
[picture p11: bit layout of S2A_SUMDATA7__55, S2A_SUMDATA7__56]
BO_ 2332557175 S2A_SUMDATA7__55: 8 SBMU
 SG_ CRC_S2A_S7_55 : 0|8@1+ (1,0) [0|255] ""  MBMU
 SG_ BAT_SOC_CorrectState_55 : 9|4@1+ (1,0) [0|15] ""  MBMU
 SG_ Status_of_Closed_Loop : 13|1@1+ (1,0) [0|1] ""  MBMU
 SG_ S2A_S7_FullDisChgFlgFromSBMU_55 : 16|1@1+ (1,0) [0|1] ""  MBMU
 SG_ S2A_S7_MaxSelfDischgRates_55 : 17|10@1+ (0.1,0) [0|102.3] "%"  MBMU,PC
 SG_ S2A_S7_MinSelfDischgRates_55 : 27|10@1+ (0.1,0) [0|102.3] "%"  MBMU,PC
 SG_ S2A_S7_AvgSelfDischgRates_55 : 37|10@1+ (0.1,0) [0|102.3] "%"  MBMU,PC
 SG_ S2A_S7_Reserved_55 : 47|1@1+ (1,0) [0|1] ""  MBMU
 SG_ S2A_S7_SOH_55 : 48|16@1+ (0.1,0) [0|6553.5] ""  MBMU

BO_ 2332557176 S2A_SUMDATA7__56: 8 SBMU
 SG_ CRC_S2A_S7_56 : 0|8@1+ (1,0) [0|255] ""  MBMU
 SG_ BAT_SOC_CorrectState_56 : 9|4@1+ (1,0) [0|15] ""  MBMU
 SG_ Status_of_Closed_Loop : 13|1@1+ (1,0) [0|1] ""  MBMU
 SG_ S2A_S7_FullDisChgFlgFromSBMU_56 : 16|1@1+ (1,0) [0|1] ""  MBMU
 SG_ S2A_S7_MaxSelfDischgRates_56 : 17|10@1+ (0.1,0) [0|102.3] "%"  MBMU,PC
 SG_ S2A_S7_MinSelfDischgRates_56 : 27|10@1+ (0.1,0) [0|102.3] "%"  MBMU,PC
 SG_ S2A_S7_AvgSelfDischgRates_56 : 37|10@1+ (0.1,0) [0|102.3] "%"  MBMU,PC
 SG_ S2A_S7_Reserved_56 : 47|1@1+ (1,0) [0|1] ""  MBMU
 SG_ S2A_S7_SOH_56 : 48|16@1+ (0.1,0) [0|6553.5] ""  MBMU

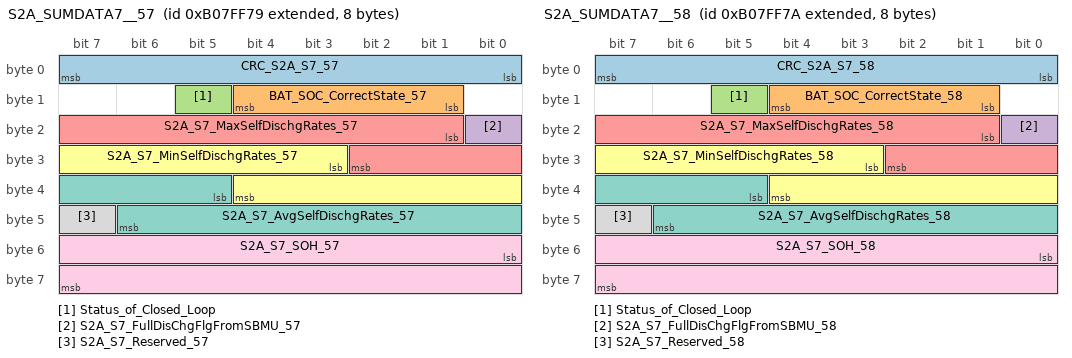
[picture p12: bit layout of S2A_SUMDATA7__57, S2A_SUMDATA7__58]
BO_ 2332557177 S2A_SUMDATA7__57: 8 SBMU
 SG_ CRC_S2A_S7_57 : 0|8@1+ (1,0) [0|255] ""  MBMU
 SG_ BAT_SOC_CorrectState_57 : 9|4@1+ (1,0) [0|15] ""  MBMU
 SG_ Status_of_Closed_Loop : 13|1@1+ (1,0) [0|1] ""  MBMU
 SG_ S2A_S7_FullDisChgFlgFromSBMU_57 : 16|1@1+ (1,0) [0|1] ""  MBMU
 SG_ S2A_S7_MaxSelfDischgRates_57 : 17|10@1+ (0.1,0) [0|102.3] "%"  MBMU,PC
 SG_ S2A_S7_MinSelfDischgRates_57 : 27|10@1+ (0.1,0) [0|102.3] "%"  MBMU,PC
 SG_ S2A_S7_AvgSelfDischgRates_57 : 37|10@1+ (0.1,0) [0|102.3] "%"  MBMU,PC
 SG_ S2A_S7_Reserved_57 : 47|1@1+ (1,0) [0|1] ""  MBMU
 SG_ S2A_S7_SOH_57 : 48|16@1+ (0.1,0) [0|6553.5] ""  MBMU

BO_ 2332557178 S2A_SUMDATA7__58: 8 SBMU
 SG_ CRC_S2A_S7_58 : 0|8@1+ (1,0) [0|255] ""  MBMU
 SG_ BAT_SOC_CorrectState_58 : 9|4@1+ (1,0) [0|15] ""  MBMU
 SG_ Status_of_Closed_Loop : 13|1@1+ (1,0) [0|1] ""  MBMU
 SG_ S2A_S7_FullDisChgFlgFromSBMU_58 : 16|1@1+ (1,0) [0|1] ""  MBMU
 SG_ S2A_S7_MaxSelfDischgRates_58 : 17|10@1+ (0.1,0) [0|102.3] "%"  MBMU,PC
 SG_ S2A_S7_MinSelfDischgRates_58 : 27|10@1+ (0.1,0) [0|102.3] "%"  MBMU,PC
 SG_ S2A_S7_AvgSelfDischgRates_58 : 37|10@1+ (0.1,0) [0|102.3] "%"  MBMU,PC
 SG_ S2A_S7_Reserved_58 : 47|1@1+ (1,0) [0|1] ""  MBMU
 SG_ S2A_S7_SOH_58 : 48|16@1+ (0.1,0) [0|6553.5] ""  MBMU

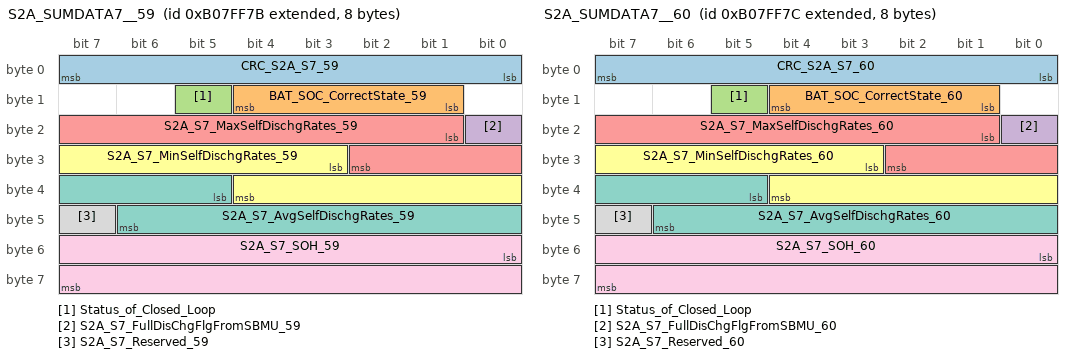
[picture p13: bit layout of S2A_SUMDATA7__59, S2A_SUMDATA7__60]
BO_ 2332557179 S2A_SUMDATA7__59: 8 SBMU
 SG_ CRC_S2A_S7_59 : 0|8@1+ (1,0) [0|255] ""  MBMU
 SG_ BAT_SOC_CorrectState_59 : 9|4@1+ (1,0) [0|15] ""  MBMU
 SG_ Status_of_Closed_Loop : 13|1@1+ (1,0) [0|1] ""  MBMU
 SG_ S2A_S7_FullDisChgFlgFromSBMU_59 : 16|1@1+ (1,0) [0|1] ""  MBMU
 SG_ S2A_S7_MaxSelfDischgRates_59 : 17|10@1+ (0.1,0) [0|102.3] "%"  MBMU,PC
 SG_ S2A_S7_MinSelfDischgRates_59 : 27|10@1+ (0.1,0) [0|102.3] "%"  MBMU,PC
 SG_ S2A_S7_AvgSelfDischgRates_59 : 37|10@1+ (0.1,0) [0|102.3] "%"  MBMU,PC
 SG_ S2A_S7_Reserved_59 : 47|1@1+ (1,0) [0|1] ""  MBMU
 SG_ S2A_S7_SOH_59 : 48|16@1+ (0.1,0) [0|6553.5] ""  MBMU

BO_ 2332557180 S2A_SUMDATA7__60: 8 SBMU
 SG_ CRC_S2A_S7_60 : 0|8@1+ (1,0) [0|255] ""  MBMU
 SG_ BAT_SOC_CorrectState_60 : 9|4@1+ (1,0) [0|15] ""  MBMU
 SG_ Status_of_Closed_Loop : 13|1@1+ (1,0) [0|1] ""  MBMU
 SG_ S2A_S7_FullDisChgFlgFromSBMU_60 : 16|1@1+ (1,0) [0|1] ""  MBMU
 SG_ S2A_S7_MaxSelfDischgRates_60 : 17|10@1+ (0.1,0) [0|102.3] "%"  MBMU,PC
 SG_ S2A_S7_MinSelfDischgRates_60 : 27|10@1+ (0.1,0) [0|102.3] "%"  MBMU,PC
 SG_ S2A_S7_AvgSelfDischgRates_60 : 37|10@1+ (0.1,0) [0|102.3] "%"  MBMU,PC
 SG_ S2A_S7_Reserved_60 : 47|1@1+ (1,0) [0|1] ""  MBMU
 SG_ S2A_S7_SOH_60 : 48|16@1+ (0.1,0) [0|6553.5] ""  MBMU

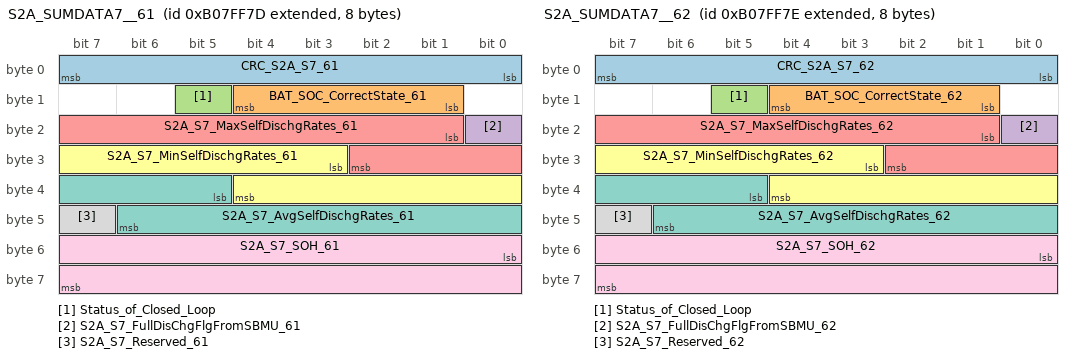
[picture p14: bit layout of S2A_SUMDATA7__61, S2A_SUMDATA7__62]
BO_ 2332557181 S2A_SUMDATA7__61: 8 SBMU
 SG_ CRC_S2A_S7_61 : 0|8@1+ (1,0) [0|255] ""  MBMU
 SG_ BAT_SOC_CorrectState_61 : 9|4@1+ (1,0) [0|15] ""  MBMU
 SG_ Status_of_Closed_Loop : 13|1@1+ (1,0) [0|1] ""  MBMU
 SG_ S2A_S7_FullDisChgFlgFromSBMU_61 : 16|1@1+ (1,0) [0|1] ""  MBMU
 SG_ S2A_S7_MaxSelfDischgRates_61 : 17|10@1+ (0.1,0) [0|102.3] "%"  MBMU,PC
 SG_ S2A_S7_MinSelfDischgRates_61 : 27|10@1+ (0.1,0) [0|102.3] "%"  MBMU,PC
 SG_ S2A_S7_AvgSelfDischgRates_61 : 37|10@1+ (0.1,0) [0|102.3] "%"  MBMU,PC
 SG_ S2A_S7_Reserved_61 : 47|1@1+ (1,0) [0|1] ""  MBMU
 SG_ S2A_S7_SOH_61 : 48|16@1+ (0.1,0) [0|6553.5] ""  MBMU

BO_ 2332557182 S2A_SUMDATA7__62: 8 SBMU
 SG_ CRC_S2A_S7_62 : 0|8@1+ (1,0) [0|255] ""  MBMU
 SG_ BAT_SOC_CorrectState_62 : 9|4@1+ (1,0) [0|15] ""  MBMU
 SG_ Status_of_Closed_Loop : 13|1@1+ (1,0) [0|1] ""  MBMU
 SG_ S2A_S7_FullDisChgFlgFromSBMU_62 : 16|1@1+ (1,0) [0|1] ""  MBMU
 SG_ S2A_S7_MaxSelfDischgRates_62 : 17|10@1+ (0.1,0) [0|102.3] "%"  MBMU,PC
 SG_ S2A_S7_MinSelfDischgRates_62 : 27|10@1+ (0.1,0) [0|102.3] "%"  MBMU,PC
 SG_ S2A_S7_AvgSelfDischgRates_62 : 37|10@1+ (0.1,0) [0|102.3] "%"  MBMU,PC
 SG_ S2A_S7_Reserved_62 : 47|1@1+ (1,0) [0|1] ""  MBMU
 SG_ S2A_S7_SOH_62 : 48|16@1+ (0.1,0) [0|6553.5] ""  MBMU

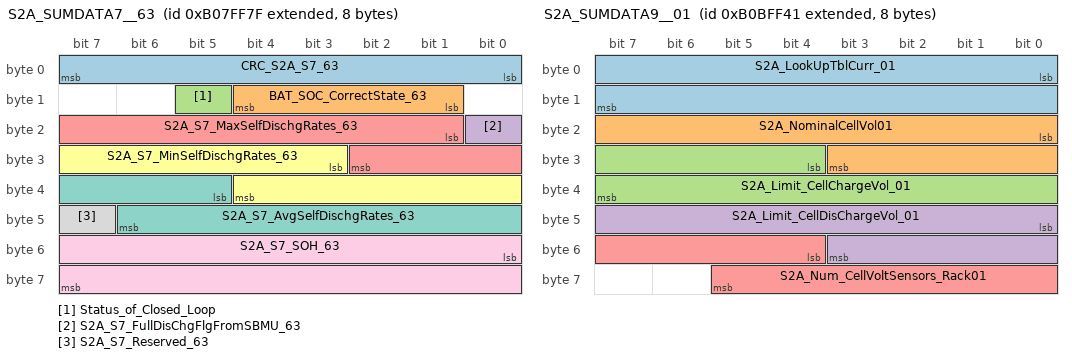
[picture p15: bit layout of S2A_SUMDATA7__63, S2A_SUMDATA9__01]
BO_ 2332557183 S2A_SUMDATA7__63: 8 SBMU
 SG_ CRC_S2A_S7_63 : 0|8@1+ (1,0) [0|255] ""  MBMU
 SG_ BAT_SOC_CorrectState_63 : 9|4@1+ (1,0) [0|15] ""  MBMU
 SG_ Status_of_Closed_Loop : 13|1@1+ (1,0) [0|1] ""  MBMU
 SG_ S2A_S7_FullDisChgFlgFromSBMU_63 : 16|1@1+ (1,0) [0|1] ""  MBMU
 SG_ S2A_S7_MaxSelfDischgRates_63 : 17|10@1+ (0.1,0) [0|102.3] "%"  MBMU,PC
 SG_ S2A_S7_MinSelfDischgRates_63 : 27|10@1+ (0.1,0) [0|102.3] "%"  MBMU,PC
 SG_ S2A_S7_AvgSelfDischgRates_63 : 37|10@1+ (0.1,0) [0|102.3] "%"  MBMU,PC
 SG_ S2A_S7_Reserved_63 : 47|1@1+ (1,0) [0|1] ""  MBMU
 SG_ S2A_S7_SOH_63 : 48|16@1+ (0.1,0) [0|6553.5] ""  MBMU

BO_ 2332622657 S2A_SUMDATA8__01: 8 SBMU
 SG_ S2A_HIS_Charge_Engery_01 : 0|32@1+ (0.1,0) [0|429496729.5] "kWh"  MBMU,PC
 SG_ S2A_HIS_Discharge_Engery_01 : 32|32@1+ (0.1,0) [0|429496729.5] "kWh"  MBMU,PC

BO_ 2332622658 S2A_SUMDATA8__02: 8 SBMU
 SG_ S2A_HIS_Charge_Engery_02 : 0|32@1+ (0.1,0) [0|429496729.5] "kWh"  MBMU,PC
 SG_ S2A_HIS_Discharge_Engery_02 : 32|32@1+ (0.1,0) [0|429496729.5] "kWh"  MBMU,PC

BO_ 2332622659 S2A_SUMDATA8__03: 8 SBMU
 SG_ S2A_HIS_Charge_Engery_03 : 0|32@1+ (0.1,0) [0|429496729.5] "kWh"  MBMU,PC
 SG_ S2A_HIS_Discharge_Engery_03 : 32|32@1+ (0.1,0) [0|429496729.5] "kWh"  MBMU,PC

BO_ 2332622660 S2A_SUMDATA8__04: 8 SBMU
 SG_ S2A_HIS_Charge_Engery_04 : 0|32@1+ (0.1,0) [0|429496729.5] "kWh"  MBMU,PC
 SG_ S2A_HIS_Discharge_Engery_04 : 32|32@1+ (0.1,0) [0|429496729.5] "kWh"  MBMU,PC

BO_ 2332622661 S2A_SUMDATA8__05: 8 SBMU
 SG_ S2A_HIS_Charge_Engery_05 : 0|32@1+ (0.1,0) [0|429496729.5] "kWh"  MBMU,PC
 SG_ S2A_HIS_Discharge_Engery_05 : 32|32@1+ (0.1,0) [0|429496729.5] "kWh"  MBMU,PC

BO_ 2332622662 S2A_SUMDATA8__06: 8 SBMU
 SG_ S2A_HIS_Charge_Engery_06 : 0|32@1+ (0.1,0) [0|429496729.5] "kWh"  MBMU,PC
 SG_ S2A_HIS_Discharge_Engery_06 : 32|32@1+ (0.1,0) [0|429496729.5] "kWh"  MBMU,PC

BO_ 2332622663 S2A_SUMDATA8__07: 8 SBMU
 SG_ S2A_HIS_Charge_Engery_07 : 0|32@1+ (0.1,0) [0|429496729.5] "kWh"  MBMU,PC
 SG_ S2A_HIS_Discharge_Engery_07 : 32|32@1+ (0.1,0) [0|429496729.5] "kWh"  MBMU,PC

BO_ 2332622664 S2A_SUMDATA8__08: 8 SBMU
 SG_ S2A_HIS_Charge_Engery_08 : 0|32@1+ (0.1,0) [0|429496729.5] "kWh"  MBMU,PC
 SG_ S2A_HIS_Discharge_Engery_08 : 32|32@1+ (0.1,0) [0|429496729.5] "kWh"  MBMU,PC

BO_ 2332622665 S2A_SUMDATA8__09: 8 SBMU
 SG_ S2A_HIS_Charge_Engery_09 : 0|32@1+ (0.1,0) [0|429496729.5] "kWh"  MBMU,PC
 SG_ S2A_HIS_Discharge_Engery_09 : 32|32@1+ (0.1,0) [0|429496729.5] "kWh"  MBMU,PC

BO_ 2332622666 S2A_SUMDATA8__10: 8 SBMU
 SG_ S2A_HIS_Charge_Engery_10 : 0|32@1+ (0.1,0) [0|429496729.5] "kWh"  MBMU,PC
 SG_ S2A_HIS_Discharge_Engery_10 : 32|32@1+ (0.1,0) [0|429496729.5] "kWh"  MBMU,PC

BO_ 2332622667 S2A_SUMDATA8__11: 8 SBMU
 SG_ S2A_HIS_Charge_Engery_11 : 0|32@1+ (0.1,0) [0|429496729.5] "kWh"  MBMU,PC
 SG_ S2A_HIS_Discharge_Engery_11 : 32|32@1+ (0.1,0) [0|429496729.5] "kWh"  MBMU,PC

BO_ 2332622668 S2A_SUMDATA8__12: 8 SBMU
 SG_ S2A_HIS_Charge_Engery_12 : 0|32@1+ (0.1,0) [0|429496729.5] "kWh"  MBMU,PC
 SG_ S2A_HIS_Discharge_Engery_12 : 32|32@1+ (0.1,0) [0|429496729.5] "kWh"  MBMU,PC

BO_ 2332622669 S2A_SUMDATA8__13: 8 SBMU
 SG_ S2A_HIS_Charge_Engery_13 : 0|32@1+ (0.1,0) [0|429496729.5] "kWh"  MBMU,PC
 SG_ S2A_HIS_Discharge_Engery_13 : 32|32@1+ (0.1,0) [0|429496729.5] "kWh"  MBMU,PC

BO_ 2332622670 S2A_SUMDATA8__14: 8 SBMU
 SG_ S2A_HIS_Charge_Engery_14 : 0|32@1+ (0.1,0) [0|429496729.5] "kWh"  MBMU,PC
 SG_ S2A_HIS_Discharge_Engery_14 : 32|32@1+ (0.1,0) [0|429496729.5] "kWh"  MBMU,PC

BO_ 2332622671 S2A_SUMDATA8__15: 8 SBMU
 SG_ S2A_HIS_Charge_Engery_15 : 0|32@1+ (0.1,0) [0|429496729.5] "kWh"  MBMU,PC
 SG_ S2A_HIS_Discharge_Engery_15 : 32|32@1+ (0.1,0) [0|429496729.5] "kWh"  MBMU,PC

BO_ 2332622672 S2A_SUMDATA8__16: 8 SBMU
 SG_ S2A_HIS_Charge_Engery_16 : 0|32@1+ (0.1,0) [0|429496729.5] "kWh"  MBMU,PC
 SG_ S2A_HIS_Discharge_Engery_16 : 32|32@1+ (0.1,0) [0|429496729.5] "kWh"  MBMU,PC

BO_ 2332622673 S2A_SUMDATA8__17: 8 SBMU
 SG_ S2A_HIS_Charge_Engery_17 : 0|32@1+ (0.1,0) [0|429496729.5] "kWh"  MBMU,PC
 SG_ S2A_HIS_Discharge_Engery_17 : 32|32@1+ (0.1,0) [0|429496729.5] "kWh"  MBMU,PC

BO_ 2332622674 S2A_SUMDATA8__18: 8 SBMU
 SG_ S2A_HIS_Charge_Engery_18 : 0|32@1+ (0.1,0) [0|429496729.5] "kWh"  MBMU,PC
 SG_ S2A_HIS_Discharge_Engery_18 : 32|32@1+ (0.1,0) [0|429496729.5] "kWh"  MBMU,PC

BO_ 2332622675 S2A_SUMDATA8__19: 8 SBMU
 SG_ S2A_HIS_Charge_Engery_19 : 0|32@1+ (0.1,0) [0|429496729.5] "kWh"  MBMU,PC
 SG_ S2A_HIS_Discharge_Engery_19 : 32|32@1+ (0.1,0) [0|429496729.5] "kWh"  MBMU,PC

BO_ 2332622676 S2A_SUMDATA8__20: 8 SBMU
 SG_ S2A_HIS_Charge_Engery_20 : 0|32@1+ (0.1,0) [0|429496729.5] "kWh"  MBMU,PC
 SG_ S2A_HIS_Discharge_Engery_20 : 32|32@1+ (0.1,0) [0|429496729.5] "kWh"  MBMU,PC

BO_ 2332622677 S2A_SUMDATA8__21: 8 SBMU
 SG_ S2A_HIS_Charge_Engery_21 : 0|32@1+ (0.1,0) [0|429496729.5] "kWh"  MBMU,PC
 SG_ S2A_HIS_Discharge_Engery_21 : 32|32@1+ (0.1,0) [0|429496729.5] "kWh"  MBMU,PC

BO_ 2332622678 S2A_SUMDATA8__22: 8 SBMU
 SG_ S2A_HIS_Charge_Engery_22 : 0|32@1+ (0.1,0) [0|429496729.5] "kWh"  MBMU,PC
 SG_ S2A_HIS_Discharge_Engery_22 : 32|32@1+ (0.1,0) [0|429496729.5] "kWh"  MBMU,PC

BO_ 2332622679 S2A_SUMDATA8__23: 8 SBMU
 SG_ S2A_HIS_Charge_Engery_23 : 0|32@1+ (0.1,0) [0|429496729.5] "kWh"  MBMU,PC
 SG_ S2A_HIS_Discharge_Engery_23 : 32|32@1+ (0.1,0) [0|429496729.5] "kWh"  MBMU,PC

BO_ 2332622680 S2A_SUMDATA8__24: 8 SBMU
 SG_ S2A_HIS_Charge_Engery_24 : 0|32@1+ (0.1,0) [0|429496729.5] "kWh"  MBMU,PC
 SG_ S2A_HIS_Discharge_Engery_24 : 32|32@1+ (0.1,0) [0|429496729.5] "kWh"  MBMU,PC

BO_ 2332622681 S2A_SUMDATA8__25: 8 SBMU
 SG_ S2A_HIS_Charge_Engery_25 : 0|32@1+ (0.1,0) [0|429496729.5] "kWh"  MBMU,PC
 SG_ S2A_HIS_Discharge_Engery_25 : 32|32@1+ (0.1,0) [0|429496729.5] "kWh"  MBMU,PC

BO_ 2332622682 S2A_SUMDATA8__26: 8 SBMU
 SG_ S2A_HIS_Charge_Engery_26 : 0|32@1+ (0.1,0) [0|429496729.5] "kWh"  MBMU,PC
 SG_ S2A_HIS_Discharge_Engery_26 : 32|32@1+ (0.1,0) [0|429496729.5] "kWh"  MBMU,PC

BO_ 2332622683 S2A_SUMDATA8__27: 8 SBMU
 SG_ S2A_HIS_Charge_Engery_27 : 0|32@1+ (0.1,0) [0|429496729.5] "kWh"  MBMU,PC
 SG_ S2A_HIS_Discharge_Engery_27 : 32|32@1+ (0.1,0) [0|429496729.5] "kWh"  MBMU,PC

BO_ 2332622684 S2A_SUMDATA8__28: 8 SBMU
 SG_ S2A_HIS_Charge_Engery_28 : 0|32@1+ (0.1,0) [0|429496729.5] "kWh"  MBMU,PC
 SG_ S2A_HIS_Discharge_Engery_28 : 32|32@1+ (0.1,0) [0|429496729.5] "kWh"  MBMU,PC

BO_ 2332622685 S2A_SUMDATA8__29: 8 SBMU
 SG_ S2A_HIS_Charge_Engery_29 : 0|32@1+ (0.1,0) [0|429496729.5] "kWh"  MBMU,PC
 SG_ S2A_HIS_Discharge_Engery_29 : 32|32@1+ (0.1,0) [0|429496729.5] "kWh"  MBMU,PC

BO_ 2332622686 S2A_SUMDATA8__30: 8 SBMU
 SG_ S2A_HIS_Charge_Engery_30 : 0|32@1+ (0.1,0) [0|429496729.5] "kWh"  MBMU,PC
 SG_ S2A_HIS_Discharge_Engery_30 : 32|32@1+ (0.1,0) [0|429496729.5] "kWh"  MBMU,PC

BO_ 2332622687 S2A_SUMDATA8__31: 8 SBMU
 SG_ S2A_HIS_Charge_Engery_31 : 0|32@1+ (0.1,0) [0|429496729.5] "kWh"  MBMU,PC
 SG_ S2A_HIS_Discharge_Engery_31 : 32|32@1+ (0.1,0) [0|429496729.5] "kWh"  MBMU,PC

BO_ 2332622688 S2A_SUMDATA8__32: 8 SBMU
 SG_ S2A_HIS_Charge_Engery_32 : 0|32@1+ (0.1,0) [0|429496729.5] "kWh"  MBMU,PC
 SG_ S2A_HIS_Discharge_Engery_32 : 32|32@1+ (0.1,0) [0|429496729.5] "kWh"  MBMU,PC

BO_ 2332622689 S2A_SUMDATA8__33: 8 SBMU
 SG_ S2A_HIS_Charge_Engery_33 : 0|32@1+ (0.1,0) [0|429496729.5] "kWh"  MBMU,PC
 SG_ S2A_HIS_Discharge_Engery_33 : 32|32@1+ (0.1,0) [0|429496729.5] "kWh"  MBMU,PC

BO_ 2332622690 S2A_SUMDATA8__34: 8 SBMU
 SG_ S2A_HIS_Charge_Engery_34 : 0|32@1+ (0.1,0) [0|429496729.5] "kWh"  MBMU,PC
 SG_ S2A_HIS_Discharge_Engery_34 : 32|32@1+ (0.1,0) [0|429496729.5] "kWh"  MBMU,PC

BO_ 2332622691 S2A_SUMDATA8__35: 8 SBMU
 SG_ S2A_HIS_Charge_Engery_35 : 0|32@1+ (0.1,0) [0|429496729.5] "kWh"  MBMU,PC
 SG_ S2A_HIS_Discharge_Engery_35 : 32|32@1+ (0.1,0) [0|429496729.5] "kWh"  MBMU,PC

BO_ 2332622692 S2A_SUMDATA8__36: 8 SBMU
 SG_ S2A_HIS_Charge_Engery_36 : 0|32@1+ (0.1,0) [0|429496729.5] "kWh"  MBMU,PC
 SG_ S2A_HIS_Discharge_Engery_36 : 32|32@1+ (0.1,0) [0|429496729.5] "kWh"  MBMU,PC

BO_ 2332622693 S2A_SUMDATA8__37: 8 SBMU
 SG_ S2A_HIS_Charge_Engery_37 : 0|32@1+ (0.1,0) [0|429496729.5] "kWh"  MBMU,PC
 SG_ S2A_HIS_Discharge_Engery_37 : 32|32@1+ (0.1,0) [0|429496729.5] "kWh"  MBMU,PC

BO_ 2332622694 S2A_SUMDATA8__38: 8 SBMU
 SG_ S2A_HIS_Charge_Engery_38 : 0|32@1+ (0.1,0) [0|429496729.5] "kWh"  MBMU,PC
 SG_ S2A_HIS_Discharge_Engery_38 : 32|32@1+ (0.1,0) [0|429496729.5] "kWh"  MBMU,PC

BO_ 2332622695 S2A_SUMDATA8__39: 8 SBMU
 SG_ S2A_HIS_Charge_Engery_39 : 0|32@1+ (0.1,0) [0|429496729.5] "kWh"  MBMU,PC
 SG_ S2A_HIS_Discharge_Engery_39 : 32|32@1+ (0.1,0) [0|429496729.5] "kWh"  MBMU,PC

BO_ 2332622696 S2A_SUMDATA8__40: 8 SBMU
 SG_ S2A_HIS_Charge_Engery_40 : 0|32@1+ (0.1,0) [0|429496729.5] "kWh"  MBMU,PC
 SG_ S2A_HIS_Discharge_Engery_40 : 32|32@1+ (0.1,0) [0|429496729.5] "kWh"  MBMU,PC

BO_ 2332622697 S2A_SUMDATA8__41: 8 SBMU
 SG_ S2A_HIS_Charge_Engery_41 : 0|32@1+ (0.1,0) [0|429496729.5] "kWh"  MBMU,PC
 SG_ S2A_HIS_Discharge_Engery_41 : 32|32@1+ (0.1,0) [0|429496729.5] "kWh"  MBMU,PC

BO_ 2332622698 S2A_SUMDATA8__42: 8 SBMU
 SG_ S2A_HIS_Charge_Engery_42 : 0|32@1+ (0.1,0) [0|429496729.5] "kWh"  MBMU,PC
 SG_ S2A_HIS_Discharge_Engery_42 : 32|32@1+ (0.1,0) [0|429496729.5] "kWh"  MBMU,PC

BO_ 2332622699 S2A_SUMDATA8__43: 8 SBMU
 SG_ S2A_HIS_Charge_Engery_43 : 0|32@1+ (0.1,0) [0|429496729.5] "kWh"  MBMU,PC
 SG_ S2A_HIS_Discharge_Engery_43 : 32|32@1+ (0.1,0) [0|429496729.5] "kWh"  MBMU,PC

BO_ 2332622700 S2A_SUMDATA8__44: 8 SBMU
 SG_ S2A_HIS_Charge_Engery_44 : 0|32@1+ (0.1,0) [0|429496729.5] "kWh"  MBMU,PC
 SG_ S2A_HIS_Discharge_Engery_44 : 32|32@1+ (0.1,0) [0|429496729.5] "kWh"  MBMU,PC

BO_ 2332622701 S2A_SUMDATA8__45: 8 SBMU
 SG_ S2A_HIS_Charge_Engery_45 : 0|32@1+ (0.1,0) [0|429496729.5] "kWh"  MBMU,PC
 SG_ S2A_HIS_Discharge_Engery_45 : 32|32@1+ (0.1,0) [0|429496729.5] "kWh"  MBMU,PC

BO_ 2332622702 S2A_SUMDATA8__46: 8 SBMU
 SG_ S2A_HIS_Charge_Engery_46 : 0|32@1+ (0.1,0) [0|429496729.5] "kWh"  MBMU,PC
 SG_ S2A_HIS_Discharge_Engery_46 : 32|32@1+ (0.1,0) [0|429496729.5] "kWh"  MBMU,PC

BO_ 2332622703 S2A_SUMDATA8__47: 8 SBMU
 SG_ S2A_HIS_Charge_Engery_47 : 0|32@1+ (0.1,0) [0|429496729.5] "kWh"  MBMU,PC
 SG_ S2A_HIS_Discharge_Engery_47 : 32|32@1+ (0.1,0) [0|429496729.5] "kWh"  MBMU,PC

BO_ 2332622704 S2A_SUMDATA8__48: 8 SBMU
 SG_ S2A_HIS_Charge_Engery_48 : 0|32@1+ (0.1,0) [0|429496729.5] "kWh"  MBMU,PC
 SG_ S2A_HIS_Discharge_Engery_48 : 32|32@1+ (0.1,0) [0|429496729.5] "kWh"  MBMU,PC

BO_ 2332622705 S2A_SUMDATA8__49: 8 SBMU
 SG_ S2A_HIS_Charge_Engery_49 : 0|32@1+ (0.1,0) [0|429496729.5] "kWh"  MBMU,PC
 SG_ S2A_HIS_Discharge_Engery_49 : 32|32@1+ (0.1,0) [0|429496729.5] "kWh"  MBMU,PC

BO_ 2332622706 S2A_SUMDATA8__50: 8 SBMU
 SG_ S2A_HIS_Charge_Engery_50 : 0|32@1+ (0.1,0) [0|429496729.5] "kWh"  MBMU,PC
 SG_ S2A_HIS_Discharge_Engery_50 : 32|32@1+ (0.1,0) [0|429496729.5] "kWh"  MBMU,PC

BO_ 2332622707 S2A_SUMDATA8__51: 8 SBMU
 SG_ S2A_HIS_Charge_Engery_51 : 0|32@1+ (0.1,0) [0|429496729.5] "kWh"  MBMU,PC
 SG_ S2A_HIS_Discharge_Engery_51 : 32|32@1+ (0.1,0) [0|429496729.5] "kWh"  MBMU,PC

BO_ 2332622708 S2A_SUMDATA8__52: 8 SBMU
 SG_ S2A_HIS_Charge_Engery_52 : 0|32@1+ (0.1,0) [0|429496729.5] "kWh"  MBMU,PC
 SG_ S2A_HIS_Discharge_Engery_52 : 32|32@1+ (0.1,0) [0|429496729.5] "kWh"  MBMU,PC

BO_ 2332622709 S2A_SUMDATA8__53: 8 SBMU
 SG_ S2A_HIS_Charge_Engery_53 : 0|32@1+ (0.1,0) [0|429496729.5] "kWh"  MBMU,PC
 SG_ S2A_HIS_Discharge_Engery_53 : 32|32@1+ (0.1,0) [0|429496729.5] "kWh"  MBMU,PC

BO_ 2332622710 S2A_SUMDATA8__54: 8 SBMU
 SG_ S2A_HIS_Charge_Engery_54 : 0|32@1+ (0.1,0) [0|429496729.5] "kWh"  MBMU,PC
 SG_ S2A_HIS_Discharge_Engery_54 : 32|32@1+ (0.1,0) [0|429496729.5] "kWh"  MBMU,PC

BO_ 2332622711 S2A_SUMDATA8__55: 8 SBMU
 SG_ S2A_HIS_Charge_Engery_55 : 0|32@1+ (0.1,0) [0|429496729.5] "kWh"  MBMU,PC
 SG_ S2A_HIS_Discharge_Engery_55 : 32|32@1+ (0.1,0) [0|429496729.5] "kWh"  MBMU,PC

BO_ 2332622712 S2A_SUMDATA8__56: 8 SBMU
 SG_ S2A_HIS_Charge_Engery_56 : 0|32@1+ (0.1,0) [0|429496729.5] "kWh"  MBMU,PC
 SG_ S2A_HIS_Discharge_Engery_56 : 32|32@1+ (0.1,0) [0|429496729.5] "kWh"  MBMU,PC

BO_ 2332622713 S2A_SUMDATA8__57: 8 SBMU
 SG_ S2A_HIS_Charge_Engery_57 : 0|32@1+ (0.1,0) [0|429496729.5] "kWh"  MBMU,PC
 SG_ S2A_HIS_Discharge_Engery_57 : 32|32@1+ (0.1,0) [0|429496729.5] "kWh"  MBMU,PC

BO_ 2332622714 S2A_SUMDATA8__58: 8 SBMU
 SG_ S2A_HIS_Charge_Engery_58 : 0|32@1+ (0.1,0) [0|429496729.5] "kWh"  MBMU,PC
 SG_ S2A_HIS_Discharge_Engery_58 : 32|32@1+ (0.1,0) [0|429496729.5] "kWh"  MBMU,PC

BO_ 2332622715 S2A_SUMDATA8__59: 8 SBMU
 SG_ S2A_HIS_Charge_Engery_59 : 0|32@1+ (0.1,0) [0|429496729.5] "kWh"  MBMU,PC
 SG_ S2A_HIS_Discharge_Engery_59 : 32|32@1+ (0.1,0) [0|429496729.5] "kWh"  MBMU,PC

BO_ 2332622716 S2A_SUMDATA8__60: 8 SBMU
 SG_ S2A_HIS_Charge_Engery_60 : 0|32@1+ (0.1,0) [0|429496729.5] "kWh"  MBMU,PC
 SG_ S2A_HIS_Discharge_Engery_60 : 32|32@1+ (0.1,0) [0|429496729.5] "kWh"  MBMU,PC

BO_ 2332622717 S2A_SUMDATA8__61: 8 SBMU
 SG_ S2A_HIS_Charge_Engery_61 : 0|32@1+ (0.1,0) [0|429496729.5] "kWh"  MBMU,PC
 SG_ S2A_HIS_Discharge_Engery_61 : 32|32@1+ (0.1,0) [0|429496729.5] "kWh"  MBMU,PC

BO_ 2332622718 S2A_SUMDATA8__62: 8 SBMU
 SG_ S2A_HIS_Charge_Engery_62 : 0|32@1+ (0.1,0) [0|429496729.5] "kWh"  MBMU,PC
 SG_ S2A_HIS_Discharge_Engery_62 : 32|32@1+ (0.1,0) [0|429496729.5] "kWh"  MBMU,PC

BO_ 2332622719 S2A_SUMDATA8__63: 8 SBMU
 SG_ S2A_HIS_Charge_Engery_63 : 0|32@1+ (0.1,0) [0|429496729.5] "kWh"  MBMU,PC
 SG_ S2A_HIS_Discharge_Engery_63 : 32|32@1+ (0.1,0) [0|429496729.5] "kWh"  MBMU,PC

BO_ 2332819265 S2A_SUMDATA9__01: 8 SBMU
 SG_ S2A_LookUpTblCurr_01 : 0|16@1+ (0.1,0) [0|6553.5] "A"  MBMU,PC
 SG_ S2A_NominalCellVol01 : 16|12@1+ (1,0) [0|4095] "mV"  MBMU,PC
 SG_ S2A_Limit_CellChargeVol_01 : 28|12@1+ (1,0) [0|4095] "mV"  MBMU,PC
 SG_ S2A_Limit_CellDisChargeVol_01 : 40|12@1+ (1,0) [0|4095] "mV"  MBMU,PC
 SG_ S2A_Num_CellVoltSensors_Rack01 : 52|10@1+ (1,0) [0|1023] ""  MBMU,PC

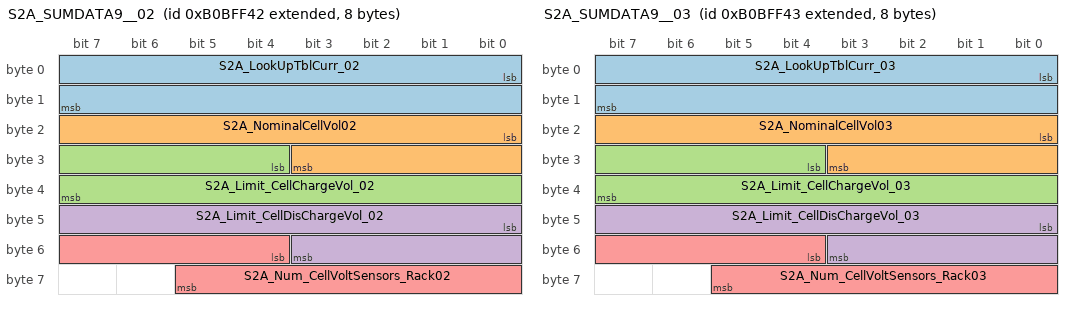
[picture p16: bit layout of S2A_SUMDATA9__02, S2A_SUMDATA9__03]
BO_ 2332819266 S2A_SUMDATA9__02: 8 SBMU
 SG_ S2A_LookUpTblCurr_02 : 0|16@1+ (0.1,0) [0|6553.5] "A"  MBMU,PC
 SG_ S2A_NominalCellVol02 : 16|12@1+ (1,0) [0|4095] "mV"  MBMU,PC
 SG_ S2A_Limit_CellChargeVol_02 : 28|12@1+ (1,0) [0|4095] "mV"  MBMU,PC
 SG_ S2A_Limit_CellDisChargeVol_02 : 40|12@1+ (1,0) [0|4095] "mV"  MBMU,PC
 SG_ S2A_Num_CellVoltSensors_Rack02 : 52|10@1+ (1,0) [0|1023] ""  MBMU,PC

BO_ 2332819267 S2A_SUMDATA9__03: 8 SBMU
 SG_ S2A_LookUpTblCurr_03 : 0|16@1+ (0.1,0) [0|6553.5] "A"  MBMU,PC
 SG_ S2A_NominalCellVol03 : 16|12@1+ (1,0) [0|4095] "mV"  MBMU,PC
 SG_ S2A_Limit_CellChargeVol_03 : 28|12@1+ (1,0) [0|4095] "mV"  MBMU,PC
 SG_ S2A_Limit_CellDisChargeVol_03 : 40|12@1+ (1,0) [0|4095] "mV"  MBMU,PC
 SG_ S2A_Num_CellVoltSensors_Rack03 : 52|10@1+ (1,0) [0|1023] ""  MBMU,PC

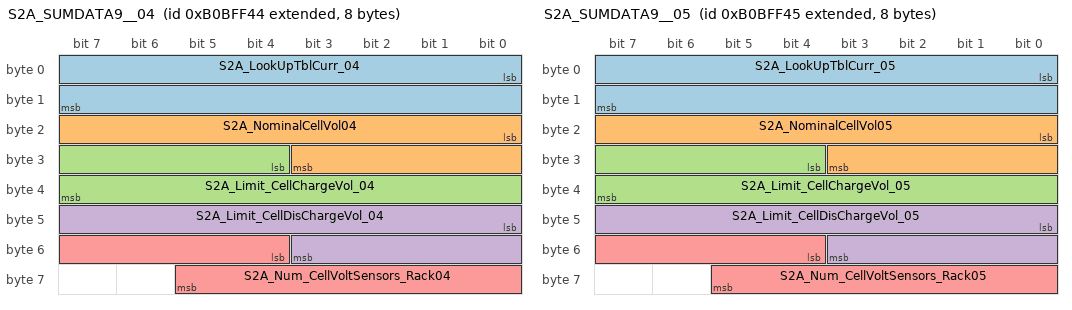
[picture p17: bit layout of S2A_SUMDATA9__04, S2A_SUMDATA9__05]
BO_ 2332819268 S2A_SUMDATA9__04: 8 SBMU
 SG_ S2A_LookUpTblCurr_04 : 0|16@1+ (0.1,0) [0|6553.5] "A"  MBMU,PC
 SG_ S2A_NominalCellVol04 : 16|12@1+ (1,0) [0|4095] "mV"  MBMU,PC
 SG_ S2A_Limit_CellChargeVol_04 : 28|12@1+ (1,0) [0|4095] "mV"  MBMU,PC
 SG_ S2A_Limit_CellDisChargeVol_04 : 40|12@1+ (1,0) [0|4095] "mV"  MBMU,PC
 SG_ S2A_Num_CellVoltSensors_Rack04 : 52|10@1+ (1,0) [0|1023] ""  MBMU,PC

BO_ 2332819269 S2A_SUMDATA9__05: 8 SBMU
 SG_ S2A_LookUpTblCurr_05 : 0|16@1+ (0.1,0) [0|6553.5] "A"  MBMU,PC
 SG_ S2A_NominalCellVol05 : 16|12@1+ (1,0) [0|4095] "mV"  MBMU,PC
 SG_ S2A_Limit_CellChargeVol_05 : 28|12@1+ (1,0) [0|4095] "mV"  MBMU,PC
 SG_ S2A_Limit_CellDisChargeVol_05 : 40|12@1+ (1,0) [0|4095] "mV"  MBMU,PC
 SG_ S2A_Num_CellVoltSensors_Rack05 : 52|10@1+ (1,0) [0|1023] ""  MBMU,PC

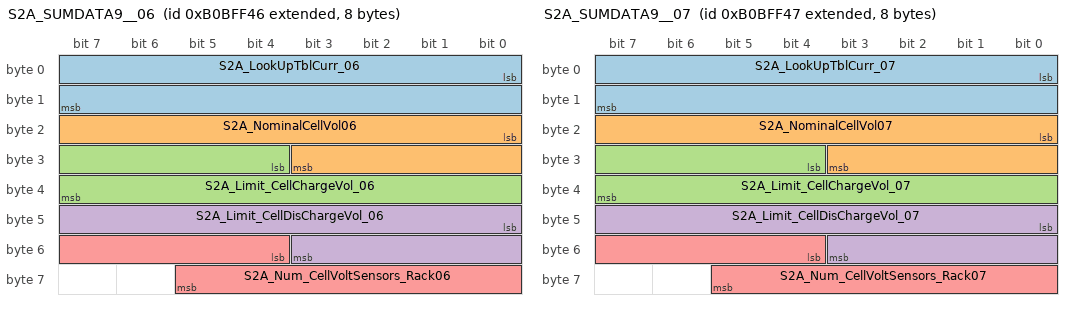
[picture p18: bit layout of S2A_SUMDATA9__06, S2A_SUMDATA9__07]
BO_ 2332819270 S2A_SUMDATA9__06: 8 SBMU
 SG_ S2A_LookUpTblCurr_06 : 0|16@1+ (0.1,0) [0|6553.5] "A"  MBMU,PC
 SG_ S2A_NominalCellVol06 : 16|12@1+ (1,0) [0|4095] "mV"  MBMU,PC
 SG_ S2A_Limit_CellChargeVol_06 : 28|12@1+ (1,0) [0|4095] "mV"  MBMU,PC
 SG_ S2A_Limit_CellDisChargeVol_06 : 40|12@1+ (1,0) [0|4095] "mV"  MBMU,PC
 SG_ S2A_Num_CellVoltSensors_Rack06 : 52|10@1+ (1,0) [0|1023] ""  MBMU,PC

BO_ 2332819271 S2A_SUMDATA9__07: 8 SBMU
 SG_ S2A_LookUpTblCurr_07 : 0|16@1+ (0.1,0) [0|6553.5] "A"  MBMU,PC
 SG_ S2A_NominalCellVol07 : 16|12@1+ (1,0) [0|4095] "mV"  MBMU,PC
 SG_ S2A_Limit_CellChargeVol_07 : 28|12@1+ (1,0) [0|4095] "mV"  MBMU,PC
 SG_ S2A_Limit_CellDisChargeVol_07 : 40|12@1+ (1,0) [0|4095] "mV"  MBMU,PC
 SG_ S2A_Num_CellVoltSensors_Rack07 : 52|10@1+ (1,0) [0|1023] ""  MBMU,PC

BO_ 2332819272 S2A_SUMDATA9__08: 8 SBMU
 SG_ S2A_LookUpTblCurr_08 : 0|16@1+ (0.1,0) [0|6553.5] "A"  MBMU,PC
 SG_ S2A_NominalCellVol08 : 16|12@1+ (1,0) [0|4095] "mV"  MBMU,PC
 SG_ S2A_Limit_CellChargeVol_08 : 28|12@1+ (1,0) [0|4095] "mV"  MBMU,PC
 SG_ S2A_Limit_CellDisChargeVol_08 : 40|12@1+ (1,0) [0|4095] "mV"  MBMU,PC
 SG_ S2A_Num_CellVoltSensors_Rack08 : 52|10@1+ (1,0) [0|1023] ""  MBMU,PC

BO_ 2332819273 S2A_SUMDATA9__09: 8 SBMU
 SG_ S2A_LookUpTblCurr_09 : 0|16@1+ (0.1,0) [0|6553.5] "A"  MBMU,PC
 SG_ S2A_NominalCellVol09 : 16|12@1+ (1,0) [0|4095] "mV"  MBMU,PC
 SG_ S2A_Limit_CellChargeVol_09 : 28|12@1+ (1,0) [0|4095] "mV"  MBMU,PC
 SG_ S2A_Limit_CellDisChargeVol_09 : 40|12@1+ (1,0) [0|4095] "mV"  MBMU,PC
 SG_ S2A_Num_CellVoltSensors_Rack09 : 52|10@1+ (1,0) [0|1023] ""  MBMU,PC

BO_ 2332819274 S2A_SUMDATA9__10: 8 SBMU
 SG_ S2A_LookUpTblCurr_10 : 0|16@1+ (0.1,0) [0|6553.5] "A"  MBMU,PC
 SG_ S2A_NominalCellVol10 : 16|12@1+ (1,0) [0|4095] "mV"  MBMU,PC
 SG_ S2A_Limit_CellChargeVol_10 : 28|12@1+ (1,0) [0|4095] "mV"  MBMU,PC
 SG_ S2A_Limit_CellDisChargeVol_10 : 40|12@1+ (1,0) [0|4095] "mV"  MBMU,PC
 SG_ S2A_Num_CellVoltSensors_Rack10 : 52|10@1+ (1,0) [0|1023] ""  MBMU,PC

BO_ 2332819275 S2A_SUMDATA9__11: 8 SBMU
 SG_ S2A_LookUpTblCurr_11 : 0|16@1+ (0.1,0) [0|6553.5] "A"  MBMU,PC
 SG_ S2A_NominalCellVol11 : 16|12@1+ (1,0) [0|4095] "mV"  MBMU,PC
 SG_ S2A_Limit_CellChargeVol_11 : 28|12@1+ (1,0) [0|4095] "mV"  MBMU,PC
 SG_ S2A_Limit_CellDisChargeVol_11 : 40|12@1+ (1,0) [0|4095] "mV"  MBMU,PC
 SG_ S2A_Num_CellVoltSensors_Rack11 : 52|10@1+ (1,0) [0|1023] ""  MBMU,PC

BO_ 2332819276 S2A_SUMDATA9__12: 8 SBMU
 SG_ S2A_LookUpTblCurr_12 : 0|16@1+ (0.1,0) [0|6553.5] "A"  MBMU,PC
 SG_ S2A_NominalCellVol12 : 16|12@1+ (1,0) [0|4095] "mV"  MBMU,PC
 SG_ S2A_Limit_CellChargeVol_12 : 28|12@1+ (1,0) [0|4095] "mV"  MBMU,PC
 SG_ S2A_Limit_CellDisChargeVol_12 : 40|12@1+ (1,0) [0|4095] "mV"  MBMU,PC
 SG_ S2A_Num_CellVoltSensors_Rack12 : 52|10@1+ (1,0) [0|1023] ""  MBMU,PC

BO_ 2332819277 S2A_SUMDATA9__13: 8 SBMU
 SG_ S2A_LookUpTblCurr_13 : 0|16@1+ (0.1,0) [0|6553.5] "A"  MBMU,PC
 SG_ S2A_NominalCellVol13 : 16|12@1+ (1,0) [0|4095] "mV"  MBMU,PC
 SG_ S2A_Limit_CellChargeVol_13 : 28|12@1+ (1,0) [0|4095] "mV"  MBMU,PC
 SG_ S2A_Limit_CellDisChargeVol_13 : 40|12@1+ (1,0) [0|4095] "mV"  MBMU,PC
 SG_ S2A_Num_CellVoltSensors_Rack13 : 52|10@1+ (1,0) [0|1023] ""  MBMU,PC

BO_ 2332819278 S2A_SUMDATA9__14: 8 SBMU
 SG_ S2A_LookUpTblCurr_14 : 0|16@1+ (0.1,0) [0|6553.5] "A"  MBMU,PC
 SG_ S2A_NominalCellVol14 : 16|12@1+ (1,0) [0|4095] "mV"  MBMU,PC
 SG_ S2A_Limit_CellChargeVol_14 : 28|12@1+ (1,0) [0|4095] "mV"  MBMU,PC
 SG_ S2A_Limit_CellDisChargeVol_14 : 40|12@1+ (1,0) [0|4095] "mV"  MBMU,PC
 SG_ S2A_Num_CellVoltSensors_Rack14 : 52|10@1+ (1,0) [0|1023] ""  MBMU,PC

BO_ 2332819279 S2A_SUMDATA9__15: 8 SBMU
 SG_ S2A_LookUpTblCurr_15 : 0|16@1+ (0.1,0) [0|6553.5] "A"  MBMU,PC
 SG_ S2A_NominalCellVol15 : 16|12@1+ (1,0) [0|4095] "mV"  MBMU,PC
 SG_ S2A_Limit_CellChargeVol_15 : 28|12@1+ (1,0) [0|4095] "mV"  MBMU,PC
 SG_ S2A_Limit_CellDisChargeVol_15 : 40|12@1+ (1,0) [0|4095] "mV"  MBMU,PC
 SG_ S2A_Num_CellVoltSensors_Rack15 : 52|10@1+ (1,0) [0|1023] ""  MBMU,PC

BO_ 2332819280 S2A_SUMDATA9__16: 8 SBMU
 SG_ S2A_LookUpTblCurr_16 : 0|16@1+ (0.1,0) [0|6553.5] "A"  MBMU,PC
 SG_ S2A_NominalCellVol16 : 16|12@1+ (1,0) [0|4095] "mV"  MBMU,PC
 SG_ S2A_Limit_CellChargeVol_16 : 28|12@1+ (1,0) [0|4095] "mV"  MBMU,PC
 SG_ S2A_Limit_CellDisChargeVol_16 : 40|12@1+ (1,0) [0|4095] "mV"  MBMU,PC
 SG_ S2A_Num_CellVoltSensors_Rack16 : 52|10@1+ (1,0) [0|1023] ""  MBMU,PC

BO_ 2332819281 S2A_SUMDATA9__17: 8 SBMU
 SG_ S2A_LookUpTblCurr_17 : 0|16@1+ (0.1,0) [0|6553.5] "A"  MBMU,PC
 SG_ S2A_NominalCellVol17 : 16|12@1+ (1,0) [0|4095] "mV"  MBMU,PC
 SG_ S2A_Limit_CellChargeVol_17 : 28|12@1+ (1,0) [0|4095] "mV"  MBMU,PC
 SG_ S2A_Limit_CellDisChargeVol_17 : 40|12@1+ (1,0) [0|4095] "mV"  MBMU,PC
 SG_ S2A_Num_CellVoltSensors_Rack17 : 52|10@1+ (1,0) [0|1023] ""  MBMU,PC

BO_ 2332819282 S2A_SUMDATA9__18: 8 SBMU
 SG_ S2A_LookUpTblCurr_18 : 0|16@1+ (0.1,0) [0|6553.5] "A"  MBMU,PC
 SG_ S2A_NominalCellVol18 : 16|12@1+ (1,0) [0|4095] "mV"  MBMU,PC
 SG_ S2A_Limit_CellChargeVol_18 : 28|12@1+ (1,0) [0|4095] "mV"  MBMU,PC
 SG_ S2A_Limit_CellDisChargeVol_18 : 40|12@1+ (1,0) [0|4095] "mV"  MBMU,PC
 SG_ S2A_Num_CellVoltSensors_Rack18 : 52|10@1+ (1,0) [0|1023] ""  MBMU,PC

BO_ 2332819283 S2A_SUMDATA9__19: 8 SBMU
 SG_ S2A_LookUpTblCurr_19 : 0|16@1+ (0.1,0) [0|6553.5] "A"  MBMU,PC
 SG_ S2A_NominalCellVol19 : 16|12@1+ (1,0) [0|4095] "mV"  MBMU,PC
 SG_ S2A_Limit_CellChargeVol_19 : 28|12@1+ (1,0) [0|4095] "mV"  MBMU,PC
 SG_ S2A_Limit_CellDisChargeVol_19 : 40|12@1+ (1,0) [0|4095] "mV"  MBMU,PC
 SG_ S2A_Num_CellVoltSensors_Rack19 : 52|10@1+ (1,0) [0|1023] ""  MBMU,PC

BO_ 2332819284 S2A_SUMDATA9__20: 8 SBMU
 SG_ S2A_LookUpTblCurr_20 : 0|16@1+ (0.1,0) [0|6553.5] "A"  MBMU,PC
 SG_ S2A_NominalCellVol20 : 16|12@1+ (1,0) [0|4095] "mV"  MBMU,PC
 SG_ S2A_Limit_CellChargeVol_20 : 28|12@1+ (1,0) [0|4095] "mV"  MBMU,PC
 SG_ S2A_Limit_CellDisChargeVol_20 : 40|12@1+ (1,0) [0|4095] "mV"  MBMU,PC
 SG_ S2A_Num_CellVoltSensors_Rack20 : 52|10@1+ (1,0) [0|1023] ""  MBMU,PC

BO_ 2332819285 S2A_SUMDATA9__21: 8 SBMU
 SG_ S2A_LookUpTblCurr_21 : 0|16@1+ (0.1,0) [0|6553.5] "A"  MBMU,PC
 SG_ S2A_NominalCellVol21 : 16|12@1+ (1,0) [0|4095] "mV"  MBMU,PC
 SG_ S2A_Limit_CellChargeVol_21 : 28|12@1+ (1,0) [0|4095] "mV"  MBMU,PC
 SG_ S2A_Limit_CellDisChargeVol_21 : 40|12@1+ (1,0) [0|4095] "mV"  MBMU,PC
 SG_ S2A_Num_CellVoltSensors_Rack21 : 52|10@1+ (1,0) [0|1023] ""  MBMU,PC

BO_ 2332819286 S2A_SUMDATA9__22: 8 SBMU
 SG_ S2A_LookUpTblCurr_22 : 0|16@1+ (0.1,0) [0|6553.5] "A"  MBMU,PC
 SG_ S2A_NominalCellVol22 : 16|12@1+ (1,0) [0|4095] "mV"  MBMU,PC
 SG_ S2A_Limit_CellChargeVol_22 : 28|12@1+ (1,0) [0|4095] "mV"  MBMU,PC
 SG_ S2A_Limit_CellDisChargeVol_22 : 40|12@1+ (1,0) [0|4095] "mV"  MBMU,PC
 SG_ S2A_Num_CellVoltSensors_Rack22 : 52|10@1+ (1,0) [0|1023] ""  MBMU,PC

BO_ 2332819287 S2A_SUMDATA9__23: 8 SBMU
 SG_ S2A_LookUpTblCurr_23 : 0|16@1+ (0.1,0) [0|6553.5] "A"  MBMU,PC
 SG_ S2A_NominalCellVol23 : 16|12@1+ (1,0) [0|4095] "mV"  MBMU,PC
 SG_ S2A_Limit_CellChargeVol_23 : 28|12@1+ (1,0) [0|4095] "mV"  MBMU,PC
 SG_ S2A_Limit_CellDisChargeVol_23 : 40|12@1+ (1,0) [0|4095] "mV"  MBMU,PC
 SG_ S2A_Num_CellVoltSensors_Rack23 : 52|10@1+ (1,0) [0|1023] ""  MBMU,PC

BO_ 2332819288 S2A_SUMDATA9__24: 8 SBMU
 SG_ S2A_LookUpTblCurr_24 : 0|16@1+ (0.1,0) [0|6553.5] "A"  MBMU,PC
 SG_ S2A_NominalCellVol24 : 16|12@1+ (1,0) [0|4095] "mV"  MBMU,PC
 SG_ S2A_Limit_CellChargeVol_24 : 28|12@1+ (1,0) [0|4095] "mV"  MBMU,PC
 SG_ S2A_Limit_CellDisChargeVol_24 : 40|12@1+ (1,0) [0|4095] "mV"  MBMU,PC
 SG_ S2A_Num_CellVoltSensors_Rack24 : 52|10@1+ (1,0) [0|1023] ""  MBMU,PC

BO_ 2332819289 S2A_SUMDATA9__25: 8 SBMU
 SG_ S2A_LookUpTblCurr_25 : 0|16@1+ (0.1,0) [0|6553.5] "A"  MBMU,PC
 SG_ S2A_NominalCellVol25 : 16|12@1+ (1,0) [0|4095] "mV"  MBMU,PC
 SG_ S2A_Limit_CellChargeVol_25 : 28|12@1+ (1,0) [0|4095] "mV"  MBMU,PC
 SG_ S2A_Limit_CellDisChargeVol_25 : 40|12@1+ (1,0) [0|4095] "mV"  MBMU,PC
 SG_ S2A_Num_CellVoltSensors_Rack25 : 52|10@1+ (1,0) [0|1023] ""  MBMU,PC

BO_ 2332819290 S2A_SUMDATA9__26: 8 SBMU
 SG_ S2A_LookUpTblCurr_26 : 0|16@1+ (0.1,0) [0|6553.5] "A"  MBMU,PC
 SG_ S2A_NominalCellVol26 : 16|12@1+ (1,0) [0|4095] "mV"  MBMU,PC
 SG_ S2A_Limit_CellChargeVol_26 : 28|12@1+ (1,0) [0|4095] "mV"  MBMU,PC
 SG_ S2A_Limit_CellDisChargeVol_26 : 40|12@1+ (1,0) [0|4095] "mV"  MBMU,PC
 SG_ S2A_Num_CellVoltSensors_Rack26 : 52|10@1+ (1,0) [0|1023] ""  MBMU,PC

BO_ 2332819291 S2A_SUMDATA9__27: 8 SBMU
 SG_ S2A_LookUpTblCurr_27 : 0|16@1+ (0.1,0) [0|6553.5] "A"  MBMU,PC
 SG_ S2A_NominalCellVol27 : 16|12@1+ (1,0) [0|4095] "mV"  MBMU,PC
 SG_ S2A_Limit_CellChargeVol_27 : 28|12@1+ (1,0) [0|4095] "mV"  MBMU,PC
 SG_ S2A_Limit_CellDisChargeVol_27 : 40|12@1+ (1,0) [0|4095] "mV"  MBMU,PC
 SG_ S2A_Num_CellVoltSensors_Rack27 : 52|10@1+ (1,0) [0|1023] ""  MBMU,PC

BO_ 2332819292 S2A_SUMDATA9__28: 8 SBMU
 SG_ S2A_LookUpTblCurr_28 : 0|16@1+ (0.1,0) [0|6553.5] "A"  MBMU,PC
 SG_ S2A_NominalCellVol28 : 16|12@1+ (1,0) [0|4095] "mV"  MBMU,PC
 SG_ S2A_Limit_CellChargeVol_28 : 28|12@1+ (1,0) [0|4095] "mV"  MBMU,PC
 SG_ S2A_Limit_CellDisChargeVol_28 : 40|12@1+ (1,0) [0|4095] "mV"  MBMU,PC
 SG_ S2A_Num_CellVoltSensors_Rack28 : 52|10@1+ (1,0) [0|1023] ""  MBMU,PC

BO_ 2332819293 S2A_SUMDATA9__29: 8 SBMU
 SG_ S2A_LookUpTblCurr_29 : 0|16@1+ (0.1,0) [0|6553.5] "A"  MBMU,PC
 SG_ S2A_NominalCellVol29 : 16|12@1+ (1,0) [0|4095] "mV"  MBMU,PC
 SG_ S2A_Limit_CellChargeVol_29 : 28|12@1+ (1,0) [0|4095] "mV"  MBMU,PC
 SG_ S2A_Limit_CellDisChargeVol_29 : 40|12@1+ (1,0) [0|4095] "mV"  MBMU,PC
 SG_ S2A_Num_CellVoltSensors_Rack29 : 52|10@1+ (1,0) [0|1023] ""  MBMU,PC

BO_ 2332819294 S2A_SUMDATA9__30: 8 SBMU
 SG_ S2A_LookUpTblCurr_30 : 0|16@1+ (0.1,0) [0|6553.5] "A"  MBMU,PC
 SG_ S2A_NominalCellVol30 : 16|12@1+ (1,0) [0|4095] "mV"  MBMU,PC
 SG_ S2A_Limit_CellChargeVol_30 : 28|12@1+ (1,0) [0|4095] "mV"  MBMU,PC
 SG_ S2A_Limit_CellDisChargeVol_30 : 40|12@1+ (1,0) [0|4095] "mV"  MBMU,PC
 SG_ S2A_Num_CellVoltSensors_Rack30 : 52|10@1+ (1,0) [0|1023] ""  MBMU,PC

BO_ 2332819295 S2A_SUMDATA9__31: 8 SBMU
 SG_ S2A_LookUpTblCurr_31 : 0|16@1+ (0.1,0) [0|6553.5] "A"  MBMU,PC
 SG_ S2A_NominalCellVol31 : 16|12@1+ (1,0) [0|4095] "mV"  MBMU,PC
 SG_ S2A_Limit_CellChargeVol_31 : 28|12@1+ (1,0) [0|4095] "mV"  MBMU,PC
 SG_ S2A_Limit_CellDisChargeVol_31 : 40|12@1+ (1,0) [0|4095] "mV"  MBMU,PC
 SG_ S2A_Num_CellVoltSensors_Rack31 : 52|10@1+ (1,0) [0|1023] ""  MBMU,PC

BO_ 2332819296 S2A_SUMDATA9__32: 8 SBMU
 SG_ S2A_LookUpTblCurr_32 : 0|16@1+ (0.1,0) [0|6553.5] "A"  MBMU,PC
 SG_ S2A_NominalCellVol32 : 16|12@1+ (1,0) [0|4095] "mV"  MBMU,PC
 SG_ S2A_Limit_CellChargeVol_32 : 28|12@1+ (1,0) [0|4095] "mV"  MBMU,PC
 SG_ S2A_Limit_CellDisChargeVol_32 : 40|12@1+ (1,0) [0|4095] "mV"  MBMU,PC
 SG_ S2A_Num_CellVoltSensors_Rack32 : 52|10@1+ (1,0) [0|1023] ""  MBMU,PC

BO_ 2332819297 S2A_SUMDATA9__33: 8 SBMU
 SG_ S2A_LookUpTblCurr_33 : 0|16@1+ (0.1,0) [0|6553.5] "A"  MBMU,PC
 SG_ S2A_NominalCellVol33 : 16|12@1+ (1,0) [0|4095] "mV"  MBMU,PC
 SG_ S2A_Limit_CellChargeVol_33 : 28|12@1+ (1,0) [0|4095] "mV"  MBMU,PC
 SG_ S2A_Limit_CellDisChargeVol_33 : 40|12@1+ (1,0) [0|4095] "mV"  MBMU,PC
 SG_ S2A_Num_CellVoltSensors_Rack33 : 52|10@1+ (1,0) [0|1023] ""  MBMU,PC

BO_ 2332819298 S2A_SUMDATA9__34: 8 SBMU
 SG_ S2A_LookUpTblCurr_34 : 0|16@1+ (0.1,0) [0|6553.5] "A"  MBMU,PC
 SG_ S2A_NominalCellVol34 : 16|12@1+ (1,0) [0|4095] "mV"  MBMU,PC
 SG_ S2A_Limit_CellChargeVol_34 : 28|12@1+ (1,0) [0|4095] "mV"  MBMU,PC
 SG_ S2A_Limit_CellDisChargeVol_34 : 40|12@1+ (1,0) [0|4095] "mV"  MBMU,PC
 SG_ S2A_Num_CellVoltSensors_Rack34 : 52|10@1+ (1,0) [0|1023] ""  MBMU,PC

BO_ 2332819299 S2A_SUMDATA9__35: 8 SBMU
 SG_ S2A_LookUpTblCurr_35 : 0|16@1+ (0.1,0) [0|6553.5] "A"  MBMU,PC
 SG_ S2A_NominalCellVol35 : 16|12@1+ (1,0) [0|4095] "mV"  MBMU,PC
 SG_ S2A_Limit_CellChargeVol_35 : 28|12@1+ (1,0) [0|4095] "mV"  MBMU,PC
 SG_ S2A_Limit_CellDisChargeVol_35 : 40|12@1+ (1,0) [0|4095] "mV"  MBMU,PC
 SG_ S2A_Num_CellVoltSensors_Rack35 : 52|10@1+ (1,0) [0|1023] ""  MBMU,PC

BO_ 2332819300 S2A_SUMDATA9__36: 8 SBMU
 SG_ S2A_LookUpTblCurr_36 : 0|16@1+ (0.1,0) [0|6553.5] "A"  MBMU,PC
 SG_ S2A_NominalCellVol36 : 16|12@1+ (1,0) [0|4095] "mV"  MBMU,PC
 SG_ S2A_Limit_CellChargeVol_36 : 28|12@1+ (1,0) [0|4095] "mV"  MBMU,PC
 SG_ S2A_Limit_CellDisChargeVol_36 : 40|12@1+ (1,0) [0|4095] "mV"  MBMU,PC
 SG_ S2A_Num_CellVoltSensors_Rack36 : 52|10@1+ (1,0) [0|1023] ""  MBMU,PC

BO_ 2332819301 S2A_SUMDATA9__37: 8 SBMU
 SG_ S2A_LookUpTblCurr_37 : 0|16@1+ (0.1,0) [0|6553.5] "A"  MBMU,PC
 SG_ S2A_NominalCellVol37 : 16|12@1+ (1,0) [0|4095] "mV"  MBMU,PC
 SG_ S2A_Limit_CellChargeVol_37 : 28|12@1+ (1,0) [0|4095] "mV"  MBMU,PC
 SG_ S2A_Limit_CellDisChargeVol_37 : 40|12@1+ (1,0) [0|4095] "mV"  MBMU,PC
 SG_ S2A_Num_CellVoltSensors_Rack37 : 52|10@1+ (1,0) [0|1023] ""  MBMU,PC

BO_ 2332819302 S2A_SUMDATA9__38: 8 SBMU
 SG_ S2A_LookUpTblCurr_38 : 0|16@1+ (0.1,0) [0|6553.5] "A"  MBMU,PC
 SG_ S2A_NominalCellVol38 : 16|12@1+ (1,0) [0|4095] "mV"  MBMU,PC
 SG_ S2A_Limit_CellChargeVol_38 : 28|12@1+ (1,0) [0|4095] "mV"  MBMU,PC
 SG_ S2A_Limit_CellDisChargeVol_38 : 40|12@1+ (1,0) [0|4095] "mV"  MBMU,PC
 SG_ S2A_Num_CellVoltSensors_Rack38 : 52|10@1+ (1,0) [0|1023] ""  MBMU,PC

BO_ 2332819303 S2A_SUMDATA9__39: 8 SBMU
 SG_ S2A_LookUpTblCurr_39 : 0|16@1+ (0.1,0) [0|6553.5] "A"  MBMU,PC
 SG_ S2A_NominalCellVol39 : 16|12@1+ (1,0) [0|4095] "mV"  MBMU,PC
 SG_ S2A_Limit_CellChargeVol_39 : 28|12@1+ (1,0) [0|4095] "mV"  MBMU,PC
 SG_ S2A_Limit_CellDisChargeVol_39 : 40|12@1+ (1,0) [0|4095] "mV"  MBMU,PC
 SG_ S2A_Num_CellVoltSensors_Rack39 : 52|10@1+ (1,0) [0|1023] ""  MBMU,PC

BO_ 2332819304 S2A_SUMDATA9__40: 8 SBMU
 SG_ S2A_LookUpTblCurr_40 : 0|16@1+ (0.1,0) [0|6553.5] "A"  MBMU,PC
 SG_ S2A_NominalCellVol40 : 16|12@1+ (1,0) [0|4095] "mV"  MBMU,PC
 SG_ S2A_Limit_CellChargeVol_40 : 28|12@1+ (1,0) [0|4095] "mV"  MBMU,PC
 SG_ S2A_Limit_CellDisChargeVol_40 : 40|12@1+ (1,0) [0|4095] "mV"  MBMU,PC
 SG_ S2A_Num_CellVoltSensors_Rack40 : 52|10@1+ (1,0) [0|1023] ""  MBMU,PC

BO_ 2332819305 S2A_SUMDATA9__41: 8 SBMU
 SG_ S2A_LookUpTblCurr_41 : 0|16@1+ (0.1,0) [0|6553.5] "A"  MBMU,PC
 SG_ S2A_NominalCellVol41 : 16|12@1+ (1,0) [0|4095] "mV"  MBMU,PC
 SG_ S2A_Limit_CellChargeVol_41 : 28|12@1+ (1,0) [0|4095] "mV"  MBMU,PC
 SG_ S2A_Limit_CellDisChargeVol_41 : 40|12@1+ (1,0) [0|4095] "mV"  MBMU,PC
 SG_ S2A_Num_CellVoltSensors_Rack41 : 52|10@1+ (1,0) [0|1023] ""  MBMU,PC

BO_ 2332819306 S2A_SUMDATA9__42: 8 SBMU
 SG_ S2A_LookUpTblCurr_42 : 0|16@1+ (0.1,0) [0|6553.5] "A"  MBMU,PC
 SG_ S2A_NominalCellVol42 : 16|12@1+ (1,0) [0|4095] "mV"  MBMU,PC
 SG_ S2A_Limit_CellChargeVol_42 : 28|12@1+ (1,0) [0|4095] "mV"  MBMU,PC
 SG_ S2A_Limit_CellDisChargeVol_42 : 40|12@1+ (1,0) [0|4095] "mV"  MBMU,PC
 SG_ S2A_Num_CellVoltSensors_Rack42 : 52|10@1+ (1,0) [0|1023] ""  MBMU,PC

BO_ 2332819307 S2A_SUMDATA9__43: 8 SBMU
 SG_ S2A_LookUpTblCurr_43 : 0|16@1+ (0.1,0) [0|6553.5] "A"  MBMU,PC
 SG_ S2A_NominalCellVol43 : 16|12@1+ (1,0) [0|4095] "mV"  MBMU,PC
 SG_ S2A_Limit_CellChargeVol_43 : 28|12@1+ (1,0) [0|4095] "mV"  MBMU,PC
 SG_ S2A_Limit_CellDisChargeVol_43 : 40|12@1+ (1,0) [0|4095] "mV"  MBMU,PC
 SG_ S2A_Num_CellVoltSensors_Rack43 : 52|10@1+ (1,0) [0|1023] ""  MBMU,PC

BO_ 2332819308 S2A_SUMDATA9__44: 8 SBMU
 SG_ S2A_LookUpTblCurr_44 : 0|16@1+ (0.1,0) [0|6553.5] "A"  MBMU,PC
 SG_ S2A_NominalCellVol44 : 16|12@1+ (1,0) [0|4095] "mV"  MBMU,PC
 SG_ S2A_Limit_CellChargeVol_44 : 28|12@1+ (1,0) [0|4095] "mV"  MBMU,PC
 SG_ S2A_Limit_CellDisChargeVol_44 : 40|12@1+ (1,0) [0|4095] "mV"  MBMU,PC
 SG_ S2A_Num_CellVoltSensors_Rack44 : 52|10@1+ (1,0) [0|1023] ""  MBMU,PC

BO_ 2332819309 S2A_SUMDATA9__45: 8 SBMU
 SG_ S2A_LookUpTblCurr_45 : 0|16@1+ (0.1,0) [0|6553.5] "A"  MBMU,PC
 SG_ S2A_NominalCellVol45 : 16|12@1+ (1,0) [0|4095] "mV"  MBMU,PC
 SG_ S2A_Limit_CellChargeVol_45 : 28|12@1+ (1,0) [0|4095] "mV"  MBMU,PC
 SG_ S2A_Limit_CellDisChargeVol_45 : 40|12@1+ (1,0) [0|4095] "mV"  MBMU,PC
 SG_ S2A_Num_CellVoltSensors_Rack45 : 52|10@1+ (1,0) [0|1023] ""  MBMU,PC

BO_ 2332819310 S2A_SUMDATA9__46: 8 SBMU
 SG_ S2A_LookUpTblCurr_46 : 0|16@1+ (0.1,0) [0|6553.5] "A"  MBMU,PC
 SG_ S2A_NominalCellVol46 : 16|12@1+ (1,0) [0|4095] "mV"  MBMU,PC
 SG_ S2A_Limit_CellChargeVol_46 : 28|12@1+ (1,0) [0|4095] "mV"  MBMU,PC
 SG_ S2A_Limit_CellDisChargeVol_46 : 40|12@1+ (1,0) [0|4095] "mV"  MBMU,PC
 SG_ S2A_Num_CellVoltSensors_Rack46 : 52|10@1+ (1,0) [0|1023] ""  MBMU,PC

BO_ 2332819311 S2A_SUMDATA9__47: 8 SBMU
 SG_ S2A_LookUpTblCurr_47 : 0|16@1+ (0.1,0) [0|6553.5] "A"  MBMU,PC
 SG_ S2A_NominalCellVol47 : 16|12@1+ (1,0) [0|4095] "mV"  MBMU,PC
 SG_ S2A_Limit_CellChargeVol_47 : 28|12@1+ (1,0) [0|4095] "mV"  MBMU,PC
 SG_ S2A_Limit_CellDisChargeVol_47 : 40|12@1+ (1,0) [0|4095] "mV"  MBMU,PC
 SG_ S2A_Num_CellVoltSensors_Rack47 : 52|10@1+ (1,0) [0|1023] ""  MBMU,PC

BO_ 2332819312 S2A_SUMDATA9__48: 8 SBMU
 SG_ S2A_LookUpTblCurr_48 : 0|16@1+ (0.1,0) [0|6553.5] "A"  MBMU,PC
 SG_ S2A_NominalCellVol48 : 16|12@1+ (1,0) [0|4095] "mV"  MBMU,PC
 SG_ S2A_Limit_CellChargeVol_48 : 28|12@1+ (1,0) [0|4095] "mV"  MBMU,PC
 SG_ S2A_Limit_CellDisChargeVol_48 : 40|12@1+ (1,0) [0|4095] "mV"  MBMU,PC
 SG_ S2A_Num_CellVoltSensors_Rack48 : 52|10@1+ (1,0) [0|1023] ""  MBMU,PC

BO_ 2332819313 S2A_SUMDATA9__49: 8 SBMU
 SG_ S2A_LookUpTblCurr_49 : 0|16@1+ (0.1,0) [0|6553.5] "A"  MBMU,PC
 SG_ S2A_NominalCellVol49 : 16|12@1+ (1,0) [0|4095] "mV"  MBMU,PC
 SG_ S2A_Limit_CellChargeVol_49 : 28|12@1+ (1,0) [0|4095] "mV"  MBMU,PC
 SG_ S2A_Limit_CellDisChargeVol_49 : 40|12@1+ (1,0) [0|4095] "mV"  MBMU,PC
 SG_ S2A_Num_CellVoltSensors_Rack49 : 52|10@1+ (1,0) [0|1023] ""  MBMU,PC

BO_ 2332819314 S2A_SUMDATA9__50: 8 SBMU
 SG_ S2A_LookUpTblCurr_50 : 0|16@1+ (0.1,0) [0|6553.5] "A"  MBMU,PC
 SG_ S2A_NominalCellVol50 : 16|12@1+ (1,0) [0|4095] "mV"  MBMU,PC
 SG_ S2A_Limit_CellChargeVol_50 : 28|12@1+ (1,0) [0|4095] "mV"  MBMU,PC
 SG_ S2A_Limit_CellDisChargeVol_50 : 40|12@1+ (1,0) [0|4095] "mV"  MBMU,PC
 SG_ S2A_Num_CellVoltSensors_Rack50 : 52|10@1+ (1,0) [0|1023] ""  MBMU,PC

BO_ 2332819315 S2A_SUMDATA9__51: 8 SBMU
 SG_ S2A_LookUpTblCurr_51 : 0|16@1+ (0.1,0) [0|6553.5] "A"  MBMU,PC
 SG_ S2A_NominalCellVol51 : 16|12@1+ (1,0) [0|4095] "mV"  MBMU,PC
 SG_ S2A_Limit_CellChargeVol_51 : 28|12@1+ (1,0) [0|4095] "mV"  MBMU,PC
 SG_ S2A_Limit_CellDisChargeVol_51 : 40|12@1+ (1,0) [0|4095] "mV"  MBMU,PC
 SG_ S2A_Num_CellVoltSensors_Rack51 : 52|10@1+ (1,0) [0|1023] ""  MBMU,PC

BO_ 2332819316 S2A_SUMDATA9__52: 8 SBMU
 SG_ S2A_LookUpTblCurr_52 : 0|16@1+ (0.1,0) [0|6553.5] "A"  MBMU,PC
 SG_ S2A_NominalCellVol52 : 16|12@1+ (1,0) [0|4095] "mV"  MBMU,PC
 SG_ S2A_Limit_CellChargeVol_52 : 28|12@1+ (1,0) [0|4095] "mV"  MBMU,PC
 SG_ S2A_Limit_CellDisChargeVol_52 : 40|12@1+ (1,0) [0|4095] "mV"  MBMU,PC
 SG_ S2A_Num_CellVoltSensors_Rack52 : 52|10@1+ (1,0) [0|1023] ""  MBMU,PC

BO_ 2332819317 S2A_SUMDATA9__53: 8 SBMU
 SG_ S2A_LookUpTblCurr_53 : 0|16@1+ (0.1,0) [0|6553.5] "A"  MBMU,PC
 SG_ S2A_NominalCellVol53 : 16|12@1+ (1,0) [0|4095] "mV"  MBMU,PC
 SG_ S2A_Limit_CellChargeVol_53 : 28|12@1+ (1,0) [0|4095] "mV"  MBMU,PC
 SG_ S2A_Limit_CellDisChargeVol_53 : 40|12@1+ (1,0) [0|4095] "mV"  MBMU,PC
 SG_ S2A_Num_CellVoltSensors_Rack53 : 52|10@1+ (1,0) [0|1023] ""  MBMU,PC

BO_ 2332819318 S2A_SUMDATA9__54: 8 SBMU
 SG_ S2A_LookUpTblCurr_54 : 0|16@1+ (0.1,0) [0|6553.5] "A"  MBMU,PC
 SG_ S2A_NominalCellVol54 : 16|12@1+ (1,0) [0|4095] "mV"  MBMU,PC
 SG_ S2A_Limit_CellChargeVol_54 : 28|12@1+ (1,0) [0|4095] "mV"  MBMU,PC
 SG_ S2A_Limit_CellDisChargeVol_54 : 40|12@1+ (1,0) [0|4095] "mV"  MBMU,PC
 SG_ S2A_Num_CellVoltSensors_Rack54 : 52|10@1+ (1,0) [0|1023] ""  MBMU,PC

BO_ 2332819319 S2A_SUMDATA9__55: 8 SBMU
 SG_ S2A_LookUpTblCurr_55 : 0|16@1+ (0.1,0) [0|6553.5] "A"  MBMU,PC
 SG_ S2A_NominalCellVol55 : 16|12@1+ (1,0) [0|4095] "mV"  MBMU,PC
 SG_ S2A_Limit_CellChargeVol_55 : 28|12@1+ (1,0) [0|4095] "mV"  MBMU,PC
 SG_ S2A_Limit_CellDisChargeVol_55 : 40|12@1+ (1,0) [0|4095] "mV"  MBMU,PC
 SG_ S2A_Num_CellVoltSensors_Rack55 : 52|10@1+ (1,0) [0|1023] ""  MBMU,PC

BO_ 2332819320 S2A_SUMDATA9__56: 8 SBMU
 SG_ S2A_LookUpTblCurr_56 : 0|16@1+ (0.1,0) [0|6553.5] "A"  MBMU,PC
 SG_ S2A_NominalCellVol56 : 16|12@1+ (1,0) [0|4095] "mV"  MBMU,PC
 SG_ S2A_Limit_CellChargeVol_56 : 28|12@1+ (1,0) [0|4095] "mV"  MBMU,PC
 SG_ S2A_Limit_CellDisChargeVol_56 : 40|12@1+ (1,0) [0|4095] "mV"  MBMU,PC
 SG_ S2A_Num_CellVoltSensors_Rack56 : 52|10@1+ (1,0) [0|1023] ""  MBMU,PC

BO_ 2332819321 S2A_SUMDATA9__57: 8 SBMU
 SG_ S2A_LookUpTblCurr_57 : 0|16@1+ (0.1,0) [0|6553.5] "A"  MBMU,PC
 SG_ S2A_NominalCellVol57 : 16|12@1+ (1,0) [0|4095] "mV"  MBMU,PC
 SG_ S2A_Limit_CellChargeVol_57 : 28|12@1+ (1,0) [0|4095] "mV"  MBMU,PC
 SG_ S2A_Limit_CellDisChargeVol_57 : 40|12@1+ (1,0) [0|4095] "mV"  MBMU,PC
 SG_ S2A_Num_CellVoltSensors_Rack57 : 52|10@1+ (1,0) [0|1023] ""  MBMU,PC

BO_ 2332819322 S2A_SUMDATA9__58: 8 SBMU
 SG_ S2A_LookUpTblCurr_58 : 0|16@1+ (0.1,0) [0|6553.5] "A"  MBMU,PC
 SG_ S2A_NominalCellVol58 : 16|12@1+ (1,0) [0|4095] "mV"  MBMU,PC
 SG_ S2A_Limit_CellChargeVol_58 : 28|12@1+ (1,0) [0|4095] "mV"  MBMU,PC
 SG_ S2A_Limit_CellDisChargeVol_58 : 40|12@1+ (1,0) [0|4095] "mV"  MBMU,PC
 SG_ S2A_Num_CellVoltSensors_Rack58 : 52|10@1+ (1,0) [0|1023] ""  MBMU,PC

BO_ 2332819323 S2A_SUMDATA9__59: 8 SBMU
 SG_ S2A_LookUpTblCurr_59 : 0|16@1+ (0.1,0) [0|6553.5] "A"  MBMU,PC
 SG_ S2A_NominalCellVol59 : 16|12@1+ (1,0) [0|4095] "mV"  MBMU,PC
 SG_ S2A_Limit_CellChargeVol_59 : 28|12@1+ (1,0) [0|4095] "mV"  MBMU,PC
 SG_ S2A_Limit_CellDisChargeVol_59 : 40|12@1+ (1,0) [0|4095] "mV"  MBMU,PC
 SG_ S2A_Num_CellVoltSensors_Rack59 : 52|10@1+ (1,0) [0|1023] ""  MBMU,PC

BO_ 2332819324 S2A_SUMDATA9__60: 8 SBMU
 SG_ S2A_LookUpTblCurr_60 : 0|16@1+ (0.1,0) [0|6553.5] "A"  MBMU,PC
 SG_ S2A_NominalCellVol60 : 16|12@1+ (1,0) [0|4095] "mV"  MBMU,PC
 SG_ S2A_Limit_CellChargeVol_60 : 28|12@1+ (1,0) [0|4095] "mV"  MBMU,PC
 SG_ S2A_Limit_CellDisChargeVol_60 : 40|12@1+ (1,0) [0|4095] "mV"  MBMU,PC
 SG_ S2A_Num_CellVoltSensors_Rack60 : 52|10@1+ (1,0) [0|1023] ""  MBMU,PC

BO_ 2332819325 S2A_SUMDATA9__61: 8 SBMU
 SG_ S2A_LookUpTblCurr_61 : 0|16@1+ (0.1,0) [0|6553.5] "A"  MBMU,PC
 SG_ S2A_NominalCellVol61 : 16|12@1+ (1,0) [0|4095] "mV"  MBMU,PC
 SG_ S2A_Limit_CellChargeVol_61 : 28|12@1+ (1,0) [0|4095] "mV"  MBMU,PC
 SG_ S2A_Limit_CellDisChargeVol_61 : 40|12@1+ (1,0) [0|4095] "mV"  MBMU,PC
 SG_ S2A_Num_CellVoltSensors_Rack61 : 52|10@1+ (1,0) [0|1023] ""  MBMU,PC

BO_ 2332819326 S2A_SUMDATA9__62: 8 SBMU
 SG_ S2A_LookUpTblCurr_62 : 0|16@1+ (0.1,0) [0|6553.5] "A"  MBMU,PC
 SG_ S2A_NominalCellVol62 : 16|12@1+ (1,0) [0|4095] "mV"  MBMU,PC
 SG_ S2A_Limit_CellChargeVol_62 : 28|12@1+ (1,0) [0|4095] "mV"  MBMU,PC
 SG_ S2A_Limit_CellDisChargeVol_62 : 40|12@1+ (1,0) [0|4095] "mV"  MBMU,PC
 SG_ S2A_Num_CellVoltSensors_Rack62 : 52|10@1+ (1,0) [0|1023] ""  MBMU,PC

BO_ 2332819327 S2A_SUMDATA9__63: 8 SBMU
 SG_ S2A_LookUpTblCurr_63 : 0|16@1+ (0.1,0) [0|6553.5] "A"  MBMU,PC
 SG_ S2A_NominalCellVol63 : 16|12@1+ (1,0) [0|4095] "mV"  MBMU,PC
 SG_ S2A_Limit_CellChargeVol_63 : 28|12@1+ (1,0) [0|4095] "mV"  MBMU,PC
 SG_ S2A_Limit_CellDisChargeVol_63 : 40|12@1+ (1,0) [0|4095] "mV"  MBMU,PC
 SG_ S2A_Num_CellVoltSensors_Rack63 : 52|10@1+ (1,0) [0|1023] ""  MBMU,PC

BO_ 2333212481 S2A_SUMDATA11__01: 8 SBMU
 SG_ S2A_BAT_I_HVS_01 : 0|16@1+ (0.1,-2000) [-2000|4553.5] "A"  MBMU,PC
 SG_ BAT_U_INNER_HVS_01 : 16|16@1+ (0.1,0) [0|6553.5] "V"  MBMU,PC
 SG_ BAT_Pwr_01 : 32|16@1+ (0.1,-2000) [-2000|4553.5] "KW"  MBMU,PC
 SG_ S2A_SBMU_FaultClass_01 : 48|3@1+ (1,0) [0|7] ""  MBMU,PC
 SG_ ExtinguishingValve_Drive : 51|1@1+ (1,0) [0|1] ""  MBMU,PC

BO_ 2333212482 S2A_SUMDATA11__02: 8 SBMU
 SG_ S2A_BAT_I_HVS_02 : 0|16@1+ (0.1,-2000) [-2000|4553.5] "A"  MBMU,PC
 SG_ BAT_U_INNER_HVS_02 : 16|16@1+ (0.1,0) [0|6553.5] "V"  MBMU,PC
 SG_ BAT_Pwr_02 : 32|16@1+ (0.1,-2000) [-2000|4553.5] "KW"  MBMU,PC
 SG_ S2A_SBMU_FaultClass_02 : 48|3@1+ (1,0) [0|7] ""  MBMU,PC
 SG_ ExtinguishingValve_Drive : 51|1@1+ (1,0) [0|1] ""  MBMU,PC

BO_ 2333212483 S2A_SUMDATA11__03: 8 SBMU
 SG_ S2A_BAT_I_HVS_03 : 0|16@1+ (0.1,-2000) [-2000|4553.5] "A"  MBMU,PC
 SG_ BAT_U_INNER_HVS_03 : 16|16@1+ (0.1,0) [0|6553.5] "V"  MBMU,PC
 SG_ BAT_Pwr_03 : 32|16@1+ (0.1,-2000) [-2000|4553.5] "KW"  MBMU,PC
 SG_ S2A_SBMU_FaultClass_03 : 48|3@1+ (1,0) [0|7] ""  MBMU,PC
 SG_ ExtinguishingValve_Drive : 51|1@1+ (1,0) [0|1] ""  MBMU,PC

BO_ 2333212484 S2A_SUMDATA11__04: 8 SBMU
 SG_ S2A_BAT_I_HVS_04 : 0|16@1+ (0.1,-2000) [-2000|4553.5] "A"  MBMU,PC
 SG_ BAT_U_INNER_HVS_04 : 16|16@1+ (0.1,0) [0|6553.5] "V"  MBMU,PC
 SG_ BAT_Pwr_04 : 32|16@1+ (0.1,-2000) [-2000|4553.5] "KW"  MBMU,PC
 SG_ S2A_SBMU_FaultClass_04 : 48|3@1+ (1,0) [0|7] ""  MBMU,PC
 SG_ ExtinguishingValve_Drive : 51|1@1+ (1,0) [0|1] ""  MBMU,PC

BO_ 2333212485 S2A_SUMDATA11__05: 8 SBMU
 SG_ S2A_BAT_I_HVS_05 : 0|16@1+ (0.1,-2000) [-2000|4553.5] "A"  MBMU,PC
 SG_ BAT_U_INNER_HVS_05 : 16|16@1+ (0.1,0) [0|6553.5] "V"  MBMU,PC
 SG_ BAT_Pwr_05 : 32|16@1+ (0.1,-2000) [-2000|4553.5] "KW"  MBMU,PC
 SG_ S2A_SBMU_FaultClass_05 : 48|3@1+ (1,0) [0|7] ""  MBMU,PC
 SG_ ExtinguishingValve_Drive : 51|1@1+ (1,0) [0|1] ""  MBMU,PC

BO_ 2333212486 S2A_SUMDATA11__06: 8 SBMU
 SG_ S2A_BAT_I_HVS_06 : 0|16@1+ (0.1,-2000) [-2000|4553.5] "A"  MBMU,PC
 SG_ BAT_U_INNER_HVS_06 : 16|16@1+ (0.1,0) [0|6553.5] "V"  MBMU,PC
 SG_ BAT_Pwr_06 : 32|16@1+ (0.1,-2000) [-2000|4553.5] "KW"  MBMU,PC
 SG_ S2A_SBMU_FaultClass_06 : 48|3@1+ (1,0) [0|7] ""  MBMU,PC
 SG_ ExtinguishingValve_Drive : 51|1@1+ (1,0) [0|1] ""  MBMU,PC

BO_ 2333212487 S2A_SUMDATA11__07: 8 SBMU
 SG_ S2A_BAT_I_HVS_07 : 0|16@1+ (0.1,-2000) [-2000|4553.5] "A"  MBMU,PC
 SG_ BAT_U_INNER_HVS_07 : 16|16@1+ (0.1,0) [0|6553.5] "V"  MBMU,PC
 SG_ BAT_Pwr_07 : 32|16@1+ (0.1,-2000) [-2000|4553.5] "KW"  MBMU,PC
 SG_ S2A_SBMU_FaultClass_07 : 48|3@1+ (1,0) [0|7] ""  MBMU,PC
 SG_ ExtinguishingValve_Drive : 51|1@1+ (1,0) [0|1] ""  MBMU,PC

BO_ 2333212488 S2A_SUMDATA11__08: 8 SBMU
 SG_ S2A_BAT_I_HVS_08 : 0|16@1+ (0.1,-2000) [-2000|4553.5] "A"  MBMU,PC
 SG_ BAT_U_INNER_HVS_08 : 16|16@1+ (0.1,0) [0|6553.5] "V"  MBMU,PC
 SG_ BAT_Pwr_08 : 32|16@1+ (0.1,-2000) [-2000|4553.5] "KW"  MBMU,PC
 SG_ S2A_SBMU_FaultClass_08 : 48|3@1+ (1,0) [0|7] ""  MBMU,PC
 SG_ ExtinguishingValve_Drive : 51|1@1+ (1,0) [0|1] ""  MBMU,PC

BO_ 2333212489 S2A_SUMDATA11__09: 8 SBMU
 SG_ S2A_BAT_I_HVS_09 : 0|16@1+ (0.1,-2000) [-2000|4553.5] "A"  MBMU,PC
 SG_ BAT_U_INNER_HVS_09 : 16|16@1+ (0.1,0) [0|6553.5] "V"  MBMU,PC
 SG_ BAT_Pwr_09 : 32|16@1+ (0.1,-2000) [-2000|4553.5] "KW"  MBMU,PC
 SG_ S2A_SBMU_FaultClass_09 : 48|3@1+ (1,0) [0|7] ""  MBMU,PC
 SG_ ExtinguishingValve_Drive : 51|1@1+ (1,0) [0|1] ""  MBMU,PC

BO_ 2333212490 S2A_SUMDATA11__10: 8 SBMU
 SG_ S2A_BAT_I_HVS_10 : 0|16@1+ (0.1,-2000) [-2000|4553.5] "A"  MBMU,PC
 SG_ BAT_U_INNER_HVS_10 : 16|16@1+ (0.1,0) [0|6553.5] "V"  MBMU,PC
 SG_ BAT_Pwr_10 : 32|16@1+ (0.1,-2000) [-2000|4553.5] "KW"  MBMU,PC
 SG_ S2A_SBMU_FaultClass_10 : 48|3@1+ (1,0) [0|7] ""  MBMU,PC
 SG_ ExtinguishingValve_Drive : 51|1@1+ (1,0) [0|1] ""  MBMU,PC

BO_ 2333212491 S2A_SUMDATA11__11: 8 SBMU
 SG_ S2A_BAT_I_HVS_11 : 0|16@1+ (0.1,-2000) [-2000|4553.5] "A"  MBMU,PC
 SG_ BAT_U_INNER_HVS_11 : 16|16@1+ (0.1,0) [0|6553.5] "V"  MBMU,PC
 SG_ BAT_Pwr_11 : 32|16@1+ (0.1,-2000) [-2000|4553.5] "KW"  MBMU,PC
 SG_ S2A_SBMU_FaultClass_11 : 48|3@1+ (1,0) [0|7] ""  MBMU,PC
 SG_ ExtinguishingValve_Drive : 51|1@1+ (1,0) [0|1] ""  MBMU,PC

BO_ 2333212492 S2A_SUMDATA11__12: 8 SBMU
 SG_ S2A_BAT_I_HVS_12 : 0|16@1+ (0.1,-2000) [-2000|4553.5] "A"  MBMU,PC
 SG_ BAT_U_INNER_HVS_12 : 16|16@1+ (0.1,0) [0|6553.5] "V"  MBMU,PC
 SG_ BAT_Pwr_12 : 32|16@1+ (0.1,-2000) [-2000|4553.5] "KW"  MBMU,PC
 SG_ S2A_SBMU_FaultClass_12 : 48|3@1+ (1,0) [0|7] ""  MBMU,PC
 SG_ ExtinguishingValve_Drive : 51|1@1+ (1,0) [0|1] ""  MBMU,PC

BO_ 2333212493 S2A_SUMDATA11__13: 8 SBMU
 SG_ S2A_BAT_I_HVS_13 : 0|16@1+ (0.1,-2000) [-2000|4553.5] "A"  MBMU,PC
 SG_ BAT_U_INNER_HVS_13 : 16|16@1+ (0.1,0) [0|6553.5] "V"  MBMU,PC
 SG_ BAT_Pwr_13 : 32|16@1+ (0.1,-2000) [-2000|4553.5] "KW"  MBMU,PC
 SG_ S2A_SBMU_FaultClass_13 : 48|3@1+ (1,0) [0|7] ""  MBMU,PC
 SG_ ExtinguishingValve_Drive : 51|1@1+ (1,0) [0|1] ""  MBMU,PC

BO_ 2333212494 S2A_SUMDATA11__14: 8 SBMU
 SG_ S2A_BAT_I_HVS_14 : 0|16@1+ (0.1,-2000) [-2000|4553.5] "A"  MBMU,PC
 SG_ BAT_U_INNER_HVS_14 : 16|16@1+ (0.1,0) [0|6553.5] "V"  MBMU,PC
 SG_ BAT_Pwr_14 : 32|16@1+ (0.1,-2000) [-2000|4553.5] "KW"  MBMU,PC
 SG_ S2A_SBMU_FaultClass_14 : 48|3@1+ (1,0) [0|7] ""  MBMU,PC
 SG_ ExtinguishingValve_Drive : 51|1@1+ (1,0) [0|1] ""  MBMU,PC

BO_ 2333212495 S2A_SUMDATA11__15: 8 SBMU
 SG_ S2A_BAT_I_HVS_15 : 0|16@1+ (0.1,-2000) [-2000|4553.5] "A"  MBMU,PC
 SG_ BAT_U_INNER_HVS_15 : 16|16@1+ (0.1,0) [0|6553.5] "V"  MBMU,PC
 SG_ BAT_Pwr_15 : 32|16@1+ (0.1,-2000) [-2000|4553.5] "KW"  MBMU,PC
 SG_ S2A_SBMU_FaultClass_15 : 48|3@1+ (1,0) [0|7] ""  MBMU,PC
 SG_ ExtinguishingValve_Drive : 51|1@1+ (1,0) [0|1] ""  MBMU,PC

BO_ 2333212496 S2A_SUMDATA11__16: 8 SBMU
 SG_ S2A_BAT_I_HVS_16 : 0|16@1+ (0.1,-2000) [-2000|4553.5] "A"  MBMU,PC
 SG_ BAT_U_INNER_HVS_16 : 16|16@1+ (0.1,0) [0|6553.5] "V"  MBMU,PC
 SG_ BAT_Pwr_16 : 32|16@1+ (0.1,-2000) [-2000|4553.5] "KW"  MBMU,PC
 SG_ S2A_SBMU_FaultClass_16 : 48|3@1+ (1,0) [0|7] ""  MBMU,PC
 SG_ ExtinguishingValve_Drive : 51|1@1+ (1,0) [0|1] ""  MBMU,PC

BO_ 2333212497 S2A_SUMDATA11__17: 8 SBMU
 SG_ S2A_BAT_I_HVS_17 : 0|16@1+ (0.1,-2000) [-2000|4553.5] "A"  MBMU,PC
 SG_ BAT_U_INNER_HVS_17 : 16|16@1+ (0.1,0) [0|6553.5] "V"  MBMU,PC
 SG_ BAT_Pwr_17 : 32|16@1+ (0.1,-2000) [-2000|4553.5] "KW"  MBMU,PC
 SG_ S2A_SBMU_FaultClass_17 : 48|3@1+ (1,0) [0|7] ""  MBMU,PC
 SG_ ExtinguishingValve_Drive : 51|1@1+ (1,0) [0|1] ""  MBMU,PC

BO_ 2333212498 S2A_SUMDATA11__18: 8 SBMU
 SG_ S2A_BAT_I_HVS_18 : 0|16@1+ (0.1,-2000) [-2000|4553.5] "A"  MBMU,PC
 SG_ BAT_U_INNER_HVS_18 : 16|16@1+ (0.1,0) [0|6553.5] "V"  MBMU,PC
 SG_ BAT_Pwr_18 : 32|16@1+ (0.1,-2000) [-2000|4553.5] "KW"  MBMU,PC
 SG_ S2A_SBMU_FaultClass_18 : 48|3@1+ (1,0) [0|7] ""  MBMU,PC
 SG_ ExtinguishingValve_Drive : 51|1@1+ (1,0) [0|1] ""  MBMU,PC

BO_ 2333212499 S2A_SUMDATA11__19: 8 SBMU
 SG_ S2A_BAT_I_HVS_19 : 0|16@1+ (0.1,-2000) [-2000|4553.5] "A"  MBMU,PC
 SG_ BAT_U_INNER_HVS_19 : 16|16@1+ (0.1,0) [0|6553.5] "V"  MBMU,PC
 SG_ BAT_Pwr_19 : 32|16@1+ (0.1,-2000) [-2000|4553.5] "KW"  MBMU,PC
 SG_ S2A_SBMU_FaultClass_19 : 48|3@1+ (1,0) [0|7] ""  MBMU,PC
 SG_ ExtinguishingValve_Drive : 51|1@1+ (1,0) [0|1] ""  MBMU,PC

BO_ 2333212500 S2A_SUMDATA11__20: 8 SBMU
 SG_ S2A_BAT_I_HVS_20 : 0|16@1+ (0.1,-2000) [-2000|4553.5] "A"  MBMU,PC
 SG_ BAT_U_INNER_HVS_20 : 16|16@1+ (0.1,0) [0|6553.5] "V"  MBMU,PC
 SG_ BAT_Pwr_20 : 32|16@1+ (0.1,-2000) [-2000|4553.5] "KW"  MBMU,PC
 SG_ S2A_SBMU_FaultClass_20 : 48|3@1+ (1,0) [0|7] ""  MBMU,PC
 SG_ ExtinguishingValve_Drive : 51|1@1+ (1,0) [0|1] ""  MBMU,PC

BO_ 2333212501 S2A_SUMDATA11__21: 8 SBMU
 SG_ S2A_BAT_I_HVS_21 : 0|16@1+ (0.1,-2000) [-2000|4553.5] "A"  MBMU,PC
 SG_ BAT_U_INNER_HVS_21 : 16|16@1+ (0.1,0) [0|6553.5] "V"  MBMU,PC
 SG_ BAT_Pwr_21 : 32|16@1+ (0.1,-2000) [-2000|4553.5] "KW"  MBMU,PC
 SG_ S2A_SBMU_FaultClass_21 : 48|3@1+ (1,0) [0|7] ""  MBMU,PC
 SG_ ExtinguishingValve_Drive : 51|1@1+ (1,0) [0|1] ""  MBMU,PC

BO_ 2333212502 S2A_SUMDATA11__22: 8 SBMU
 SG_ S2A_BAT_I_HVS_22 : 0|16@1+ (0.1,-2000) [-2000|4553.5] "A"  MBMU,PC
 SG_ BAT_U_INNER_HVS_22 : 16|16@1+ (0.1,0) [0|6553.5] "V"  MBMU,PC
 SG_ BAT_Pwr_22 : 32|16@1+ (0.1,-2000) [-2000|4553.5] "KW"  MBMU,PC
 SG_ S2A_SBMU_FaultClass_22 : 48|3@1+ (1,0) [0|7] ""  MBMU,PC
 SG_ ExtinguishingValve_Drive : 51|1@1+ (1,0) [0|1] ""  MBMU,PC

BO_ 2333212503 S2A_SUMDATA11__23: 8 SBMU
 SG_ S2A_BAT_I_HVS_23 : 0|16@1+ (0.1,-2000) [-2000|4553.5] "A"  MBMU,PC
 SG_ BAT_U_INNER_HVS_23 : 16|16@1+ (0.1,0) [0|6553.5] "V"  MBMU,PC
 SG_ BAT_Pwr_23 : 32|16@1+ (0.1,-2000) [-2000|4553.5] "KW"  MBMU,PC
 SG_ S2A_SBMU_FaultClass_23 : 48|3@1+ (1,0) [0|7] ""  MBMU,PC
 SG_ ExtinguishingValve_Drive : 51|1@1+ (1,0) [0|1] ""  MBMU,PC

BO_ 2333212504 S2A_SUMDATA11__24: 8 SBMU
 SG_ S2A_BAT_I_HVS_24 : 0|16@1+ (0.1,-2000) [-2000|4553.5] "A"  MBMU,PC
 SG_ BAT_U_INNER_HVS_24 : 16|16@1+ (0.1,0) [0|6553.5] "V"  MBMU,PC
 SG_ BAT_Pwr_24 : 32|16@1+ (0.1,-2000) [-2000|4553.5] "KW"  MBMU,PC
 SG_ S2A_SBMU_FaultClass_24 : 48|3@1+ (1,0) [0|7] ""  MBMU,PC
 SG_ ExtinguishingValve_Drive : 51|1@1+ (1,0) [0|1] ""  MBMU,PC

BO_ 2333212505 S2A_SUMDATA11__25: 8 SBMU
 SG_ S2A_BAT_I_HVS_25 : 0|16@1+ (0.1,-2000) [-2000|4553.5] "A"  MBMU,PC
 SG_ BAT_U_INNER_HVS_25 : 16|16@1+ (0.1,0) [0|6553.5] "V"  MBMU,PC
 SG_ BAT_Pwr_25 : 32|16@1+ (0.1,-2000) [-2000|4553.5] "KW"  MBMU,PC
 SG_ S2A_SBMU_FaultClass_25 : 48|3@1+ (1,0) [0|7] ""  MBMU,PC
 SG_ ExtinguishingValve_Drive : 51|1@1+ (1,0) [0|1] ""  MBMU,PC

BO_ 2333212506 S2A_SUMDATA11__26: 8 SBMU
 SG_ S2A_BAT_I_HVS_26 : 0|16@1+ (0.1,-2000) [-2000|4553.5] "A"  MBMU,PC
 SG_ BAT_U_INNER_HVS_26 : 16|16@1+ (0.1,0) [0|6553.5] "V"  MBMU,PC
 SG_ BAT_Pwr_26 : 32|16@1+ (0.1,-2000) [-2000|4553.5] "KW"  MBMU,PC
 SG_ S2A_SBMU_FaultClass_26 : 48|3@1+ (1,0) [0|7] ""  MBMU,PC
 SG_ ExtinguishingValve_Drive : 51|1@1+ (1,0) [0|1] ""  MBMU,PC

BO_ 2333212507 S2A_SUMDATA11__27: 8 SBMU
 SG_ S2A_BAT_I_HVS_27 : 0|16@1+ (0.1,-2000) [-2000|4553.5] "A"  MBMU,PC
 SG_ BAT_U_INNER_HVS_27 : 16|16@1+ (0.1,0) [0|6553.5] "V"  MBMU,PC
 SG_ BAT_Pwr_27 : 32|16@1+ (0.1,-2000) [-2000|4553.5] "KW"  MBMU,PC
 SG_ S2A_SBMU_FaultClass_27 : 48|3@1+ (1,0) [0|7] ""  MBMU,PC
 SG_ ExtinguishingValve_Drive : 51|1@1+ (1,0) [0|1] ""  MBMU,PC

BO_ 2333212508 S2A_SUMDATA11__28: 8 SBMU
 SG_ S2A_BAT_I_HVS_28 : 0|16@1+ (0.1,-2000) [-2000|4553.5] "A"  MBMU,PC
 SG_ BAT_U_INNER_HVS_28 : 16|16@1+ (0.1,0) [0|6553.5] "V"  MBMU,PC
 SG_ BAT_Pwr_28 : 32|16@1+ (0.1,-2000) [-2000|4553.5] "KW"  MBMU,PC
 SG_ S2A_SBMU_FaultClass_28 : 48|3@1+ (1,0) [0|7] ""  MBMU,PC
 SG_ ExtinguishingValve_Drive : 51|1@1+ (1,0) [0|1] ""  MBMU,PC

BO_ 2333212509 S2A_SUMDATA11__29: 8 SBMU
 SG_ S2A_BAT_I_HVS_29 : 0|16@1+ (0.1,-2000) [-2000|4553.5] "A"  MBMU,PC
 SG_ BAT_U_INNER_HVS_29 : 16|16@1+ (0.1,0) [0|6553.5] "V"  MBMU,PC
 SG_ BAT_Pwr_29 : 32|16@1+ (0.1,-2000) [-2000|4553.5] "KW"  MBMU,PC
 SG_ S2A_SBMU_FaultClass_29 : 48|3@1+ (1,0) [0|7] ""  MBMU,PC
 SG_ ExtinguishingValve_Drive : 51|1@1+ (1,0) [0|1] ""  MBMU,PC

BO_ 2333212510 S2A_SUMDATA11__30: 8 SBMU
 SG_ S2A_BAT_I_HVS_30 : 0|16@1+ (0.1,-2000) [-2000|4553.5] "A"  MBMU,PC
 SG_ BAT_U_INNER_HVS_30 : 16|16@1+ (0.1,0) [0|6553.5] "V"  MBMU,PC
 SG_ BAT_Pwr_30 : 32|16@1+ (0.1,-2000) [-2000|4553.5] "KW"  MBMU,PC
 SG_ S2A_SBMU_FaultClass_30 : 48|3@1+ (1,0) [0|7] ""  MBMU,PC
 SG_ ExtinguishingValve_Drive : 51|1@1+ (1,0) [0|1] ""  MBMU,PC

BO_ 2333212511 S2A_SUMDATA11__31: 8 SBMU
 SG_ S2A_BAT_I_HVS_31 : 0|16@1+ (0.1,-2000) [-2000|4553.5] "A"  MBMU,PC
 SG_ BAT_U_INNER_HVS_31 : 16|16@1+ (0.1,0) [0|6553.5] "V"  MBMU,PC
 SG_ BAT_Pwr_31 : 32|16@1+ (0.1,-2000) [-2000|4553.5] "KW"  MBMU,PC
 SG_ S2A_SBMU_FaultClass_31 : 48|3@1+ (1,0) [0|7] ""  MBMU,PC
 SG_ ExtinguishingValve_Drive : 51|1@1+ (1,0) [0|1] ""  MBMU,PC

BO_ 2333212512 S2A_SUMDATA11__32: 8 SBMU
 SG_ S2A_BAT_I_HVS_32 : 0|16@1+ (0.1,-2000) [-2000|4553.5] "A"  MBMU,PC
 SG_ BAT_U_INNER_HVS_32 : 16|16@1+ (0.1,0) [0|6553.5] "V"  MBMU,PC
 SG_ BAT_Pwr_32 : 32|16@1+ (0.1,-2000) [-2000|4553.5] "KW"  MBMU,PC
 SG_ S2A_SBMU_FaultClass_32 : 48|3@1+ (1,0) [0|7] ""  MBMU,PC
 SG_ ExtinguishingValve_Drive : 51|1@1+ (1,0) [0|1] ""  MBMU,PC

BO_ 2333212513 S2A_SUMDATA11__33: 8 SBMU
 SG_ S2A_BAT_I_HVS_33 : 0|16@1+ (0.1,-2000) [-2000|4553.5] "A"  MBMU,PC
 SG_ BAT_U_INNER_HVS_33 : 16|16@1+ (0.1,0) [0|6553.5] "V"  MBMU,PC
 SG_ BAT_Pwr_33 : 32|16@1+ (0.1,-2000) [-2000|4553.5] "KW"  MBMU,PC
 SG_ S2A_SBMU_FaultClass_33 : 48|3@1+ (1,0) [0|7] ""  MBMU,PC
 SG_ ExtinguishingValve_Drive : 51|1@1+ (1,0) [0|1] ""  MBMU,PC

BO_ 2333212514 S2A_SUMDATA11__34: 8 SBMU
 SG_ S2A_BAT_I_HVS_34 : 0|16@1+ (0.1,-2000) [-2000|4553.5] "A"  MBMU,PC
 SG_ BAT_U_INNER_HVS_34 : 16|16@1+ (0.1,0) [0|6553.5] "V"  MBMU,PC
 SG_ BAT_Pwr_34 : 32|16@1+ (0.1,-2000) [-2000|4553.5] "KW"  MBMU,PC
 SG_ S2A_SBMU_FaultClass_34 : 48|3@1+ (1,0) [0|7] ""  MBMU,PC
 SG_ ExtinguishingValve_Drive : 51|1@1+ (1,0) [0|1] ""  MBMU,PC

BO_ 2333212515 S2A_SUMDATA11__35: 8 SBMU
 SG_ S2A_BAT_I_HVS_35 : 0|16@1+ (0.1,-2000) [-2000|4553.5] "A"  MBMU,PC
 SG_ BAT_U_INNER_HVS_35 : 16|16@1+ (0.1,0) [0|6553.5] "V"  MBMU,PC
 SG_ BAT_Pwr_35 : 32|16@1+ (0.1,-2000) [-2000|4553.5] "KW"  MBMU,PC
 SG_ S2A_SBMU_FaultClass_35 : 48|3@1+ (1,0) [0|7] ""  MBMU,PC
 SG_ ExtinguishingValve_Drive : 51|1@1+ (1,0) [0|1] ""  MBMU,PC

BO_ 2333212516 S2A_SUMDATA11__36: 8 SBMU
 SG_ S2A_BAT_I_HVS_36 : 0|16@1+ (0.1,-2000) [-2000|4553.5] "A"  MBMU,PC
 SG_ BAT_U_INNER_HVS_36 : 16|16@1+ (0.1,0) [0|6553.5] "V"  MBMU,PC
 SG_ BAT_Pwr_36 : 32|16@1+ (0.1,-2000) [-2000|4553.5] "KW"  MBMU,PC
 SG_ S2A_SBMU_FaultClass_36 : 48|3@1+ (1,0) [0|7] ""  MBMU,PC
 SG_ ExtinguishingValve_Drive : 51|1@1+ (1,0) [0|1] ""  MBMU,PC

BO_ 2333212517 S2A_SUMDATA11__37: 8 SBMU
 SG_ S2A_BAT_I_HVS_37 : 0|16@1+ (0.1,-2000) [-2000|4553.5] "A"  MBMU,PC
 SG_ BAT_U_INNER_HVS_37 : 16|16@1+ (0.1,0) [0|6553.5] "V"  MBMU,PC
 SG_ BAT_Pwr_37 : 32|16@1+ (0.1,-2000) [-2000|4553.5] "KW"  MBMU,PC
 SG_ S2A_SBMU_FaultClass_37 : 48|3@1+ (1,0) [0|7] ""  MBMU,PC
 SG_ ExtinguishingValve_Drive : 51|1@1+ (1,0) [0|1] ""  MBMU,PC

BO_ 2333212518 S2A_SUMDATA11__38: 8 SBMU
 SG_ S2A_BAT_I_HVS_38 : 0|16@1+ (0.1,-2000) [-2000|4553.5] "A"  MBMU,PC
 SG_ BAT_U_INNER_HVS_38 : 16|16@1+ (0.1,0) [0|6553.5] "V"  MBMU,PC
 SG_ BAT_Pwr_38 : 32|16@1+ (0.1,-2000) [-2000|4553.5] "KW"  MBMU,PC
 SG_ S2A_SBMU_FaultClass_38 : 48|3@1+ (1,0) [0|7] ""  MBMU,PC
 SG_ ExtinguishingValve_Drive : 51|1@1+ (1,0) [0|1] ""  MBMU,PC

BO_ 2333212519 S2A_SUMDATA11__39: 8 SBMU
 SG_ S2A_BAT_I_HVS_39 : 0|16@1+ (0.1,-2000) [-2000|4553.5] "A"  MBMU,PC
 SG_ BAT_U_INNER_HVS_39 : 16|16@1+ (0.1,0) [0|6553.5] "V"  MBMU,PC
 SG_ BAT_Pwr_39 : 32|16@1+ (0.1,-2000) [-2000|4553.5] "KW"  MBMU,PC
 SG_ S2A_SBMU_FaultClass_39 : 48|3@1+ (1,0) [0|7] ""  MBMU,PC
 SG_ ExtinguishingValve_Drive : 51|1@1+ (1,0) [0|1] ""  MBMU,PC

BO_ 2333212520 S2A_SUMDATA11__40: 8 SBMU
 SG_ S2A_BAT_I_HVS_40 : 0|16@1+ (0.1,-2000) [-2000|4553.5] "A"  MBMU,PC
 SG_ BAT_U_INNER_HVS_40 : 16|16@1+ (0.1,0) [0|6553.5] "V"  MBMU,PC
 SG_ BAT_Pwr_40 : 32|16@1+ (0.1,-2000) [-2000|4553.5] "KW"  MBMU,PC
 SG_ S2A_SBMU_FaultClass_40 : 48|3@1+ (1,0) [0|7] ""  MBMU,PC
 SG_ ExtinguishingValve_Drive : 51|1@1+ (1,0) [0|1] ""  MBMU,PC

BO_ 2333212521 S2A_SUMDATA11__41: 8 SBMU
 SG_ S2A_BAT_I_HVS_41 : 0|16@1+ (0.1,-2000) [-2000|4553.5] "A"  MBMU,PC
 SG_ BAT_U_INNER_HVS_41 : 16|16@1+ (0.1,0) [0|6553.5] "V"  MBMU,PC
 SG_ BAT_Pwr_41 : 32|16@1+ (0.1,-2000) [-2000|4553.5] "KW"  MBMU,PC
 SG_ S2A_SBMU_FaultClass_41 : 48|3@1+ (1,0) [0|7] ""  MBMU,PC
 SG_ ExtinguishingValve_Drive : 51|1@1+ (1,0) [0|1] ""  MBMU,PC

BO_ 2333212522 S2A_SUMDATA11__42: 8 SBMU
 SG_ S2A_BAT_I_HVS_42 : 0|16@1+ (0.1,-2000) [-2000|4553.5] "A"  MBMU,PC
 SG_ BAT_U_INNER_HVS_42 : 16|16@1+ (0.1,0) [0|6553.5] "V"  MBMU,PC
 SG_ BAT_Pwr_42 : 32|16@1+ (0.1,-2000) [-2000|4553.5] "KW"  MBMU,PC
 SG_ S2A_SBMU_FaultClass_42 : 48|3@1+ (1,0) [0|7] ""  MBMU,PC
 SG_ ExtinguishingValve_Drive : 51|1@1+ (1,0) [0|1] ""  MBMU,PC

BO_ 2333212523 S2A_SUMDATA11__43: 8 SBMU
 SG_ S2A_BAT_I_HVS_43 : 0|16@1+ (0.1,-2000) [-2000|4553.5] "A"  MBMU,PC
 SG_ BAT_U_INNER_HVS_43 : 16|16@1+ (0.1,0) [0|6553.5] "V"  MBMU,PC
 SG_ BAT_Pwr_43 : 32|16@1+ (0.1,-2000) [-2000|4553.5] "KW"  MBMU,PC
 SG_ S2A_SBMU_FaultClass_43 : 48|3@1+ (1,0) [0|7] ""  MBMU,PC
 SG_ ExtinguishingValve_Drive : 51|1@1+ (1,0) [0|1] ""  MBMU,PC

BO_ 2333212524 S2A_SUMDATA11__44: 8 SBMU
 SG_ S2A_BAT_I_HVS_44 : 0|16@1+ (0.1,-2000) [-2000|4553.5] "A"  MBMU,PC
 SG_ BAT_U_INNER_HVS_44 : 16|16@1+ (0.1,0) [0|6553.5] "V"  MBMU,PC
 SG_ BAT_Pwr_44 : 32|16@1+ (0.1,-2000) [-2000|4553.5] "KW"  MBMU,PC
 SG_ S2A_SBMU_FaultClass_44 : 48|3@1+ (1,0) [0|7] ""  MBMU,PC
 SG_ ExtinguishingValve_Drive : 51|1@1+ (1,0) [0|1] ""  MBMU,PC

BO_ 2333212525 S2A_SUMDATA11__45: 8 SBMU
 SG_ S2A_BAT_I_HVS_45 : 0|16@1+ (0.1,-2000) [-2000|4553.5] "A"  MBMU,PC
 SG_ BAT_U_INNER_HVS_45 : 16|16@1+ (0.1,0) [0|6553.5] "V"  MBMU,PC
 SG_ BAT_Pwr_45 : 32|16@1+ (0.1,-2000) [-2000|4553.5] "KW"  MBMU,PC
 SG_ S2A_SBMU_FaultClass_45 : 48|3@1+ (1,0) [0|7] ""  MBMU,PC
 SG_ ExtinguishingValve_Drive : 51|1@1+ (1,0) [0|1] ""  MBMU,PC

BO_ 2333212526 S2A_SUMDATA11__46: 8 SBMU
 SG_ S2A_BAT_I_HVS_46 : 0|16@1+ (0.1,-2000) [-2000|4553.5] "A"  MBMU,PC
 SG_ BAT_U_INNER_HVS_46 : 16|16@1+ (0.1,0) [0|6553.5] "V"  MBMU,PC
 SG_ BAT_Pwr_46 : 32|16@1+ (0.1,-2000) [-2000|4553.5] "KW"  MBMU,PC
 SG_ S2A_SBMU_FaultClass_46 : 48|3@1+ (1,0) [0|7] ""  MBMU,PC
 SG_ ExtinguishingValve_Drive : 51|1@1+ (1,0) [0|1] ""  MBMU,PC

BO_ 2333212527 S2A_SUMDATA11__47: 8 SBMU
 SG_ S2A_BAT_I_HVS_47 : 0|16@1+ (0.1,-2000) [-2000|4553.5] "A"  MBMU,PC
 SG_ BAT_U_INNER_HVS_47 : 16|16@1+ (0.1,0) [0|6553.5] "V"  MBMU,PC
 SG_ BAT_Pwr_47 : 32|16@1+ (0.1,-2000) [-2000|4553.5] "KW"  MBMU,PC
 SG_ S2A_SBMU_FaultClass_47 : 48|3@1+ (1,0) [0|7] ""  MBMU,PC
 SG_ ExtinguishingValve_Drive : 51|1@1+ (1,0) [0|1] ""  MBMU,PC

BO_ 2333212528 S2A_SUMDATA11__48: 8 SBMU
 SG_ S2A_BAT_I_HVS_48 : 0|16@1+ (0.1,-2000) [-2000|4553.5] "A"  MBMU,PC
 SG_ BAT_U_INNER_HVS_48 : 16|16@1+ (0.1,0) [0|6553.5] "V"  MBMU,PC
 SG_ BAT_Pwr_48 : 32|16@1+ (0.1,-2000) [-2000|4553.5] "KW"  MBMU,PC
 SG_ S2A_SBMU_FaultClass_48 : 48|3@1+ (1,0) [0|7] ""  MBMU,PC
 SG_ ExtinguishingValve_Drive : 51|1@1+ (1,0) [0|1] ""  MBMU,PC

BO_ 2333212529 S2A_SUMDATA11__49: 8 SBMU
 SG_ S2A_BAT_I_HVS_49 : 0|16@1+ (0.1,-2000) [-2000|4553.5] "A"  MBMU,PC
 SG_ BAT_U_INNER_HVS_49 : 16|16@1+ (0.1,0) [0|6553.5] "V"  MBMU,PC
 SG_ BAT_Pwr_49 : 32|16@1+ (0.1,-2000) [-2000|4553.5] "KW"  MBMU,PC
 SG_ S2A_SBMU_FaultClass_49 : 48|3@1+ (1,0) [0|7] ""  MBMU,PC
 SG_ ExtinguishingValve_Drive : 51|1@1+ (1,0) [0|1] ""  MBMU,PC

BO_ 2333212530 S2A_SUMDATA11__50: 8 SBMU
 SG_ S2A_BAT_I_HVS_50 : 0|16@1+ (0.1,-2000) [-2000|4553.5] "A"  MBMU,PC
 SG_ BAT_U_INNER_HVS_50 : 16|16@1+ (0.1,0) [0|6553.5] "V"  MBMU,PC
 SG_ BAT_Pwr_50 : 32|16@1+ (0.1,-2000) [-2000|4553.5] "KW"  MBMU,PC
 SG_ S2A_SBMU_FaultClass_50 : 48|3@1+ (1,0) [0|7] ""  MBMU,PC
 SG_ ExtinguishingValve_Drive : 51|1@1+ (1,0) [0|1] ""  MBMU,PC

BO_ 2333212531 S2A_SUMDATA11__51: 8 SBMU
 SG_ S2A_BAT_I_HVS_51 : 0|16@1+ (0.1,-2000) [-2000|4553.5] "A"  MBMU,PC
 SG_ BAT_U_INNER_HVS_51 : 16|16@1+ (0.1,0) [0|6553.5] "V"  MBMU,PC
 SG_ BAT_Pwr_51 : 32|16@1+ (0.1,-2000) [-2000|4553.5] "KW"  MBMU,PC
 SG_ S2A_SBMU_FaultClass_51 : 48|3@1+ (1,0) [0|7] ""  MBMU,PC
 SG_ ExtinguishingValve_Drive : 51|1@1+ (1,0) [0|1] ""  MBMU,PC

BO_ 2333212532 S2A_SUMDATA11__52: 8 SBMU
 SG_ S2A_BAT_I_HVS_52 : 0|16@1+ (0.1,-2000) [-2000|4553.5] "A"  MBMU,PC
 SG_ BAT_U_INNER_HVS_52 : 16|16@1+ (0.1,0) [0|6553.5] "V"  MBMU,PC
 SG_ BAT_Pwr_52 : 32|16@1+ (0.1,-2000) [-2000|4553.5] "KW"  MBMU,PC
 SG_ S2A_SBMU_FaultClass_52 : 48|3@1+ (1,0) [0|7] ""  MBMU,PC
 SG_ ExtinguishingValve_Drive : 51|1@1+ (1,0) [0|1] ""  MBMU,PC

BO_ 2333212533 S2A_SUMDATA11__53: 8 SBMU
 SG_ S2A_BAT_I_HVS_53 : 0|16@1+ (0.1,-2000) [-2000|4553.5] "A"  MBMU,PC
 SG_ BAT_U_INNER_HVS_53 : 16|16@1+ (0.1,0) [0|6553.5] "V"  MBMU,PC
 SG_ BAT_Pwr_53 : 32|16@1+ (0.1,-2000) [-2000|4553.5] "KW"  MBMU,PC
 SG_ S2A_SBMU_FaultClass_53 : 48|3@1+ (1,0) [0|7] ""  MBMU,PC
 SG_ ExtinguishingValve_Drive : 51|1@1+ (1,0) [0|1] ""  MBMU,PC

BO_ 2333212534 S2A_SUMDATA11__54: 8 SBMU
 SG_ S2A_BAT_I_HVS_54 : 0|16@1+ (0.1,-2000) [-2000|4553.5] "A"  MBMU,PC
 SG_ BAT_U_INNER_HVS_54 : 16|16@1+ (0.1,0) [0|6553.5] "V"  MBMU,PC
 SG_ BAT_Pwr_54 : 32|16@1+ (0.1,-2000) [-2000|4553.5] "KW"  MBMU,PC
 SG_ S2A_SBMU_FaultClass_54 : 48|3@1+ (1,0) [0|7] ""  MBMU,PC
 SG_ ExtinguishingValve_Drive : 51|1@1+ (1,0) [0|1] ""  MBMU,PC

BO_ 2333212535 S2A_SUMDATA11__55: 8 SBMU
 SG_ S2A_BAT_I_HVS_55 : 0|16@1+ (0.1,-2000) [-2000|4553.5] "A"  MBMU,PC
 SG_ BAT_U_INNER_HVS_55 : 16|16@1+ (0.1,0) [0|6553.5] "V"  MBMU,PC
 SG_ BAT_Pwr_55 : 32|16@1+ (0.1,-2000) [-2000|4553.5] "KW"  MBMU,PC
 SG_ S2A_SBMU_FaultClass_55 : 48|3@1+ (1,0) [0|7] ""  MBMU,PC
 SG_ ExtinguishingValve_Drive : 51|1@1+ (1,0) [0|1] ""  MBMU,PC

BO_ 2333212536 S2A_SUMDATA11__56: 8 SBMU
 SG_ S2A_BAT_I_HVS_56 : 0|16@1+ (0.1,-2000) [-2000|4553.5] "A"  MBMU,PC
 SG_ BAT_U_INNER_HVS_56 : 16|16@1+ (0.1,0) [0|6553.5] "V"  MBMU,PC
 SG_ BAT_Pwr_56 : 32|16@1+ (0.1,-2000) [-2000|4553.5] "KW"  MBMU,PC
 SG_ S2A_SBMU_FaultClass_56 : 48|3@1+ (1,0) [0|7] ""  MBMU,PC
 SG_ ExtinguishingValve_Drive : 51|1@1+ (1,0) [0|1] ""  MBMU,PC

BO_ 2333212537 S2A_SUMDATA11__57: 8 SBMU
 SG_ S2A_BAT_I_HVS_57 : 0|16@1+ (0.1,-2000) [-2000|4553.5] "A"  MBMU,PC
 SG_ BAT_U_INNER_HVS_57 : 16|16@1+ (0.1,0) [0|6553.5] "V"  MBMU,PC
 SG_ BAT_Pwr_57 : 32|16@1+ (0.1,-2000) [-2000|4553.5] "KW"  MBMU,PC
 SG_ S2A_SBMU_FaultClass_57 : 48|3@1+ (1,0) [0|7] ""  MBMU,PC
 SG_ ExtinguishingValve_Drive : 51|1@1+ (1,0) [0|1] ""  MBMU,PC

BO_ 2333212538 S2A_SUMDATA11__58: 8 SBMU
 SG_ S2A_BAT_I_HVS_58 : 0|16@1+ (0.1,-2000) [-2000|4553.5] "A"  MBMU,PC
 SG_ BAT_U_INNER_HVS_58 : 16|16@1+ (0.1,0) [0|6553.5] "V"  MBMU,PC
 SG_ BAT_Pwr_58 : 32|16@1+ (0.1,-2000) [-2000|4553.5] "KW"  MBMU,PC
 SG_ S2A_SBMU_FaultClass_58 : 48|3@1+ (1,0) [0|7] ""  MBMU,PC
 SG_ ExtinguishingValve_Drive : 51|1@1+ (1,0) [0|1] ""  MBMU,PC

BO_ 2333212539 S2A_SUMDATA11__59: 8 SBMU
 SG_ S2A_BAT_I_HVS_59 : 0|16@1+ (0.1,-2000) [-2000|4553.5] "A"  MBMU,PC
 SG_ BAT_U_INNER_HVS_59 : 16|16@1+ (0.1,0) [0|6553.5] "V"  MBMU,PC
 SG_ BAT_Pwr_59 : 32|16@1+ (0.1,-2000) [-2000|4553.5] "KW"  MBMU,PC
 SG_ S2A_SBMU_FaultClass_59 : 48|3@1+ (1,0) [0|7] ""  MBMU,PC
 SG_ ExtinguishingValve_Drive : 51|1@1+ (1,0) [0|1] ""  MBMU,PC

BO_ 2333212540 S2A_SUMDATA11__60: 8 SBMU
 SG_ S2A_BAT_I_HVS_60 : 0|16@1+ (0.1,-2000) [-2000|4553.5] "A"  MBMU,PC
 SG_ BAT_U_INNER_HVS_60 : 16|16@1+ (0.1,0) [0|6553.5] "V"  MBMU,PC
 SG_ BAT_Pwr_60 : 32|16@1+ (0.1,-2000) [-2000|4553.5] "KW"  MBMU,PC
 SG_ S2A_SBMU_FaultClass_60 : 48|3@1+ (1,0) [0|7] ""  MBMU,PC
 SG_ ExtinguishingValve_Drive : 51|1@1+ (1,0) [0|1] ""  MBMU,PC

BO_ 2333212541 S2A_SUMDATA11__61: 8 SBMU
 SG_ S2A_BAT_I_HVS_61 : 0|16@1+ (0.1,-2000) [-2000|4553.5] "A"  MBMU,PC
 SG_ BAT_U_INNER_HVS_61 : 16|16@1+ (0.1,0) [0|6553.5] "V"  MBMU,PC
 SG_ BAT_Pwr_61 : 32|16@1+ (0.1,-2000) [-2000|4553.5] "KW"  MBMU,PC
 SG_ S2A_SBMU_FaultClass_61 : 48|3@1+ (1,0) [0|7] ""  MBMU,PC
 SG_ ExtinguishingValve_Drive : 51|1@1+ (1,0) [0|1] ""  MBMU,PC

BO_ 2333212542 S2A_SUMDATA11__62: 8 SBMU
 SG_ S2A_BAT_I_HVS_62 : 0|16@1+ (0.1,-2000) [-2000|4553.5] "A"  MBMU,PC
 SG_ BAT_U_INNER_HVS_62 : 16|16@1+ (0.1,0) [0|6553.5] "V"  MBMU,PC
 SG_ BAT_Pwr_62 : 32|16@1+ (0.1,-2000) [-2000|4553.5] "KW"  MBMU,PC
 SG_ S2A_SBMU_FaultClass_62 : 48|3@1+ (1,0) [0|7] ""  MBMU,PC
 SG_ ExtinguishingValve_Drive : 51|1@1+ (1,0) [0|1] ""  MBMU,PC

BO_ 2333212543 S2A_SUMDATA11__63: 8 SBMU
 SG_ S2A_BAT_I_HVS_63 : 0|16@1+ (0.1,-2000) [-2000|4553.5] "A"  MBMU,PC
 SG_ BAT_U_INNER_HVS_63 : 16|16@1+ (0.1,0) [0|6553.5] "V"  MBMU,PC
 SG_ BAT_Pwr_63 : 32|16@1+ (0.1,-2000) [-2000|4553.5] "KW"  MBMU,PC
 SG_ S2A_SBMU_FaultClass_63 : 48|3@1+ (1,0) [0|7] ""  MBMU,PC
 SG_ ExtinguishingValve_Drive : 51|1@1+ (1,0) [0|1] ""  MBMU,PC

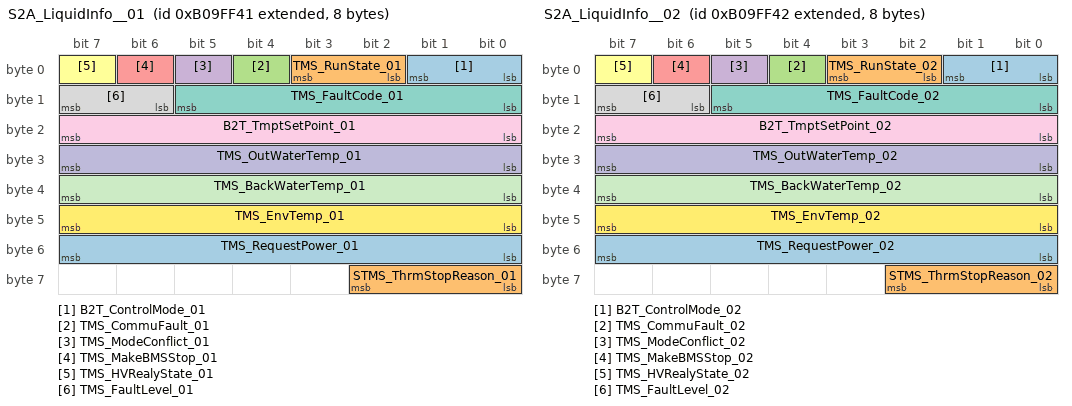
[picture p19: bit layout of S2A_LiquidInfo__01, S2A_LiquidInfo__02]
BO_ 2332688193 S2A_LiquidInfo__01: 8 SBMU
 SG_ B2T_ControlMode_01 : 0|2@1+ (1,0) [0|3] ""  MBMU,PC
 SG_ TMS_RunState_01 : 2|2@1+ (1,0) [0|3] ""  MBMU,PC
 SG_ TMS_CommuFault_01 : 4|1@1+ (1,0) [0|1] ""  MBMU,PC
 SG_ TMS_ModeConflict_01 : 5|1@1+ (1,0) [0|1] ""  MBMU,PC
 SG_ TMS_MakeBMSStop_01 : 6|1@1+ (1,0) [0|1] ""  MBMU,PC
 SG_ TMS_HVRealyState_01 : 7|1@1+ (1,0) [0|1] ""  MBMU,PC
 SG_ TMS_FaultCode_01 : 8|6@1+ (1,0) [0|63] ""  MBMU,PC
 SG_ TMS_FaultLevel_01 : 14|2@1+ (1,0) [0|3] ""  MBMU,PC
 SG_ B2T_TmptSetPoint_01 : 16|8@1+ (1,-50) [-50|210] "℃"  MBMU,PC
 SG_ TMS_OutWaterTemp_01 : 24|8@1+ (1,-50) [-50|210] "℃"  MBMU,PC
 SG_ TMS_BackWaterTemp_01 : 32|8@1+ (1,-50) [-50|210] "℃"  MBMU,PC
 SG_ TMS_EnvTemp_01 : 40|8@1+ (1,-50) [-50|210] "℃"  MBMU,PC
 SG_ TMS_RequestPower_01 : 48|8@1+ (0.1,0) [0|100] "Kw"  MBMU,PC
 SG_ STMS_ThrmStopReason_01 : 56|3@1+ (1,0) [0|3] ""  MBMU,PC

BO_ 2332688194 S2A_LiquidInfo__02: 8 SBMU
 SG_ B2T_ControlMode_02 : 0|2@1+ (1,0) [0|3] ""  MBMU,PC
 SG_ TMS_RunState_02 : 2|2@1+ (1,0) [0|3] ""  MBMU,PC
 SG_ TMS_CommuFault_02 : 4|1@1+ (1,0) [0|1] ""  MBMU,PC
 SG_ TMS_ModeConflict_02 : 5|1@1+ (1,0) [0|1] ""  MBMU,PC
 SG_ TMS_MakeBMSStop_02 : 6|1@1+ (1,0) [0|1] ""  MBMU,PC
 SG_ TMS_HVRealyState_02 : 7|1@1+ (1,0) [0|1] ""  MBMU,PC
 SG_ TMS_FaultCode_02 : 8|6@1+ (1,0) [0|63] ""  MBMU,PC
 SG_ TMS_FaultLevel_02 : 14|2@1+ (1,0) [0|3] ""  MBMU,PC
 SG_ B2T_TmptSetPoint_02 : 16|8@1+ (1,-50) [-50|210] "℃"  MBMU,PC
 SG_ TMS_OutWaterTemp_02 : 24|8@1+ (1,-50) [-50|210] "℃"  MBMU,PC
 SG_ TMS_BackWaterTemp_02 : 32|8@1+ (1,-50) [-50|210] "℃"  MBMU,PC
 SG_ TMS_EnvTemp_02 : 40|8@1+ (1,-50) [-50|210] "℃"  MBMU,PC
 SG_ TMS_RequestPower_02 : 48|8@1+ (0.1,0) [0|100] "Kw"  MBMU,PC
 SG_ STMS_ThrmStopReason_02 : 56|3@1+ (1,0) [0|3] ""  MBMU,PC

CM_ SG_ 2332557153 CRC_S2A_S7_33 "S2A概要数据7 的CRC";
CM_ SG_ 2332557153 BAT_SOC_CorrectState_33 "SOC修正状态（最后一次）";
CM_ SG_ 2332557153 Status_of_Closed_Loop "闭环算法开启状态";
CM_ SG_ 2332557153 S2A_S7_FullDisChgFlgFromSBMU_33 "满放标志位";
CM_ SG_ 2332557153 S2A_S7_MaxSelfDischgRates_33 "电池簇电芯月自放电率最大值";
CM_ SG_ 2332557153 S2A_S7_MinSelfDischgRates_33 "电池簇电芯月自放电率最小值";
CM_ SG_ 2332557153 S2A_S7_AvgSelfDischgRates_33 "电池簇电芯月自放电率平均值";
CM_ SG_ 2332557153 S2A_S7_SOH_33 "平均SOH ";
CM_ SG_ 2332557154 CRC_S2A_S7_34 "S2A概要数据7 的CRC";
CM_ SG_ 2332557154 BAT_SOC_CorrectState_34 "SOC修正状态（最后一次）";
CM_ SG_ 2332557154 Status_of_Closed_Loop "闭环算法开启状态";
CM_ SG_ 2332557154 S2A_S7_FullDisChgFlgFromSBMU_34 "满放标志位";
CM_ SG_ 2332557154 S2A_S7_MaxSelfDischgRates_34 "电池簇电芯月自放电率最大值";
CM_ SG_ 2332557154 S2A_S7_MinSelfDischgRates_34 "电池簇电芯月自放电率最小值";
CM_ SG_ 2332557154 S2A_S7_AvgSelfDischgRates_34 "电池簇电芯月自放电率平均值";
CM_ SG_ 2332557154 S2A_S7_SOH_34 "平均SOH ";
CM_ SG_ 2332557155 CRC_S2A_S7_35 "S2A概要数据7 的CRC";
CM_ SG_ 2332557155 BAT_SOC_CorrectState_35 "SOC修正状态（最后一次）";
CM_ SG_ 2332557155 Status_of_Closed_Loop "闭环算法开启状态";
CM_ SG_ 2332557155 S2A_S7_FullDisChgFlgFromSBMU_35 "满放标志位";
CM_ SG_ 2332557155 S2A_S7_MaxSelfDischgRates_35 "电池簇电芯月自放电率最大值";
CM_ SG_ 2332557155 S2A_S7_MinSelfDischgRates_35 "电池簇电芯月自放电率最小值";
CM_ SG_ 2332557155 S2A_S7_AvgSelfDischgRates_35 "电池簇电芯月自放电率平均值";
CM_ SG_ 2332557155 S2A_S7_SOH_35 "平均SOH ";
CM_ SG_ 2332557156 CRC_S2A_S7_36 "S2A概要数据7 的CRC";
CM_ SG_ 2332557156 BAT_SOC_CorrectState_36 "SOC修正状态（最后一次）";
CM_ SG_ 2332557156 Status_of_Closed_Loop "闭环算法开启状态";
CM_ SG_ 2332557156 S2A_S7_FullDisChgFlgFromSBMU_36 "满放标志位";
CM_ SG_ 2332557156 S2A_S7_MaxSelfDischgRates_36 "电池簇电芯月自放电率最大值";
CM_ SG_ 2332557156 S2A_S7_MinSelfDischgRates_36 "电池簇电芯月自放电率最小值";
CM_ SG_ 2332557156 S2A_S7_AvgSelfDischgRates_36 "电池簇电芯月自放电率平均值";
CM_ SG_ 2332557156 S2A_S7_SOH_36 "平均SOH ";
CM_ SG_ 2332557157 CRC_S2A_S7_37 "S2A概要数据7 的CRC";
CM_ SG_ 2332557157 BAT_SOC_CorrectState_37 "SOC修正状态（最后一次）";
CM_ SG_ 2332557157 Status_of_Closed_Loop "闭环算法开启状态";
CM_ SG_ 2332557157 S2A_S7_FullDisChgFlgFromSBMU_37 "满放标志位";
CM_ SG_ 2332557157 S2A_S7_MaxSelfDischgRates_37 "电池簇电芯月自放电率最大值";
CM_ SG_ 2332557157 S2A_S7_MinSelfDischgRates_37 "电池簇电芯月自放电率最小值";
CM_ SG_ 2332557157 S2A_S7_AvgSelfDischgRates_37 "电池簇电芯月自放电率平均值";
CM_ SG_ 2332557157 S2A_S7_SOH_37 "平均SOH ";
CM_ SG_ 2332557158 CRC_S2A_S7_38 "S2A概要数据7 的CRC";
CM_ SG_ 2332557158 BAT_SOC_CorrectState_38 "SOC修正状态（最后一次）";
CM_ SG_ 2332557158 Status_of_Closed_Loop "闭环算法开启状态";
CM_ SG_ 2332557158 S2A_S7_FullDisChgFlgFromSBMU_38 "满放标志位";
CM_ SG_ 2332557158 S2A_S7_MaxSelfDischgRates_38 "电池簇电芯月自放电率最大值";
CM_ SG_ 2332557158 S2A_S7_MinSelfDischgRates_38 "电池簇电芯月自放电率最小值";
CM_ SG_ 2332557158 S2A_S7_AvgSelfDischgRates_38 "电池簇电芯月自放电率平均值";
CM_ SG_ 2332557158 S2A_S7_SOH_38 "平均SOH ";
CM_ SG_ 2332557159 CRC_S2A_S7_39 "S2A概要数据7 的CRC";
CM_ SG_ 2332557159 BAT_SOC_CorrectState_39 "SOC修正状态（最后一次）";
CM_ SG_ 2332557159 Status_of_Closed_Loop "闭环算法开启状态";
CM_ SG_ 2332557159 S2A_S7_FullDisChgFlgFromSBMU_39 "满放标志位";
CM_ SG_ 2332557159 S2A_S7_MaxSelfDischgRates_39 "电池簇电芯月自放电率最大值";
CM_ SG_ 2332557159 S2A_S7_MinSelfDischgRates_39 "电池簇电芯月自放电率最小值";
CM_ SG_ 2332557159 S2A_S7_AvgSelfDischgRates_39 "电池簇电芯月自放电率平均值";
CM_ SG_ 2332557159 S2A_S7_SOH_39 "平均SOH ";
CM_ SG_ 2332557160 CRC_S2A_S7_40 "S2A概要数据7 的CRC";
CM_ SG_ 2332557160 BAT_SOC_CorrectState_40 "SOC修正状态（最后一次）";
CM_ SG_ 2332557160 Status_of_Closed_Loop "闭环算法开启状态";
CM_ SG_ 2332557160 S2A_S7_FullDisChgFlgFromSBMU_40 "满放标志位";
CM_ SG_ 2332557160 S2A_S7_MaxSelfDischgRates_40 "电池簇电芯月自放电率最大值";
CM_ SG_ 2332557160 S2A_S7_MinSelfDischgRates_40 "电池簇电芯月自放电率最小值";
CM_ SG_ 2332557160 S2A_S7_AvgSelfDischgRates_40 "电池簇电芯月自放电率平均值";
CM_ SG_ 2332557160 S2A_S7_SOH_40 "平均SOH ";
CM_ SG_ 2332557161 CRC_S2A_S7_41 "S2A概要数据7 的CRC";
CM_ SG_ 2332557161 BAT_SOC_CorrectState_41 "SOC修正状态（最后一次）";
CM_ SG_ 2332557161 Status_of_Closed_Loop "闭环算法开启状态";
CM_ SG_ 2332557161 S2A_S7_FullDisChgFlgFromSBMU_41 "满放标志位";
CM_ SG_ 2332557161 S2A_S7_MaxSelfDischgRates_41 "电池簇电芯月自放电率最大值";
CM_ SG_ 2332557161 S2A_S7_MinSelfDischgRates_41 "电池簇电芯月自放电率最小值";
CM_ SG_ 2332557161 S2A_S7_AvgSelfDischgRates_41 "电池簇电芯月自放电率平均值";
CM_ SG_ 2332557161 S2A_S7_SOH_41 "平均SOH ";
CM_ SG_ 2332557162 CRC_S2A_S7_42 "S2A概要数据7 的CRC";
CM_ SG_ 2332557162 BAT_SOC_CorrectState_42 "SOC修正状态（最后一次）";
CM_ SG_ 2332557162 Status_of_Closed_Loop "闭环算法开启状态";
CM_ SG_ 2332557162 S2A_S7_FullDisChgFlgFromSBMU_42 "满放标志位";
CM_ SG_ 2332557162 S2A_S7_MaxSelfDischgRates_42 "电池簇电芯月自放电率最大值";
CM_ SG_ 2332557162 S2A_S7_MinSelfDischgRates_42 "电池簇电芯月自放电率最小值";
CM_ SG_ 2332557162 S2A_S7_AvgSelfDischgRates_42 "电池簇电芯月自放电率平均值";
CM_ SG_ 2332557162 S2A_S7_SOH_42 "平均SOH ";
CM_ SG_ 2332557163 CRC_S2A_S7_43 "S2A概要数据7 的CRC";
CM_ SG_ 2332557163 BAT_SOC_CorrectState_43 "SOC修正状态（最后一次）";
CM_ SG_ 2332557163 Status_of_Closed_Loop "闭环算法开启状态";
CM_ SG_ 2332557163 S2A_S7_FullDisChgFlgFromSBMU_43 "满放标志位";
CM_ SG_ 2332557163 S2A_S7_MaxSelfDischgRates_43 "电池簇电芯月自放电率最大值";
CM_ SG_ 2332557163 S2A_S7_MinSelfDischgRates_43 "电池簇电芯月自放电率最小值";
CM_ SG_ 2332557163 S2A_S7_AvgSelfDischgRates_43 "电池簇电芯月自放电率平均值";
CM_ SG_ 2332557163 S2A_S7_SOH_43 "平均SOH ";
CM_ SG_ 2332557164 CRC_S2A_S7_44 "S2A概要数据7 的CRC";
CM_ SG_ 2332557164 BAT_SOC_CorrectState_44 "SOC修正状态（最后一次）";
CM_ SG_ 2332557164 Status_of_Closed_Loop "闭环算法开启状态";
CM_ SG_ 2332557164 S2A_S7_FullDisChgFlgFromSBMU_44 "满放标志位";
CM_ SG_ 2332557164 S2A_S7_MaxSelfDischgRates_44 "电池簇电芯月自放电率最大值";
CM_ SG_ 2332557164 S2A_S7_MinSelfDischgRates_44 "电池簇电芯月自放电率最小值";
CM_ SG_ 2332557164 S2A_S7_AvgSelfDischgRates_44 "电池簇电芯月自放电率平均值";
CM_ SG_ 2332557164 S2A_S7_SOH_44 "平均SOH ";
CM_ SG_ 2332557165 CRC_S2A_S7_45 "S2A概要数据7 的CRC";
CM_ SG_ 2332557165 BAT_SOC_CorrectState_45 "SOC修正状态（最后一次）";
CM_ SG_ 2332557165 Status_of_Closed_Loop "闭环算法开启状态";
CM_ SG_ 2332557165 S2A_S7_FullDisChgFlgFromSBMU_45 "满放标志位";
CM_ SG_ 2332557165 S2A_S7_MaxSelfDischgRates_45 "电池簇电芯月自放电率最大值";
CM_ SG_ 2332557165 S2A_S7_MinSelfDischgRates_45 "电池簇电芯月自放电率最小值";
CM_ SG_ 2332557165 S2A_S7_AvgSelfDischgRates_45 "电池簇电芯月自放电率平均值";
CM_ SG_ 2332557165 S2A_S7_SOH_45 "平均SOH ";
CM_ SG_ 2332557166 CRC_S2A_S7_46 "S2A概要数据7 的CRC";
CM_ SG_ 2332557166 BAT_SOC_CorrectState_46 "SOC修正状态（最后一次）";
CM_ SG_ 2332557166 Status_of_Closed_Loop "闭环算法开启状态";
CM_ SG_ 2332557166 S2A_S7_FullDisChgFlgFromSBMU_46 "满放标志位";
CM_ SG_ 2332557166 S2A_S7_MaxSelfDischgRates_46 "电池簇电芯月自放电率最大值";
CM_ SG_ 2332557166 S2A_S7_MinSelfDischgRates_46 "电池簇电芯月自放电率最小值";
CM_ SG_ 2332557166 S2A_S7_AvgSelfDischgRates_46 "电池簇电芯月自放电率平均值";
CM_ SG_ 2332557166 S2A_S7_SOH_46 "平均SOH ";
CM_ SG_ 2332557167 CRC_S2A_S7_47 "S2A概要数据7 的CRC";
CM_ SG_ 2332557167 BAT_SOC_CorrectState_47 "SOC修正状态（最后一次）";
CM_ SG_ 2332557167 Status_of_Closed_Loop "闭环算法开启状态";
CM_ SG_ 2332557167 S2A_S7_FullDisChgFlgFromSBMU_47 "满放标志位";
CM_ SG_ 2332557167 S2A_S7_MaxSelfDischgRates_47 "电池簇电芯月自放电率最大值";
CM_ SG_ 2332557167 S2A_S7_MinSelfDischgRates_47 "电池簇电芯月自放电率最小值";
CM_ SG_ 2332557167 S2A_S7_AvgSelfDischgRates_47 "电池簇电芯月自放电率平均值";
CM_ SG_ 2332557167 S2A_S7_SOH_47 "平均SOH ";
CM_ SG_ 2332557168 CRC_S2A_S7_48 "S2A概要数据7 的CRC";
CM_ SG_ 2332557168 BAT_SOC_CorrectState_48 "SOC修正状态（最后一次）";
CM_ SG_ 2332557168 Status_of_Closed_Loop "闭环算法开启状态";
CM_ SG_ 2332557168 S2A_S7_FullDisChgFlgFromSBMU_48 "满放标志位";
CM_ SG_ 2332557168 S2A_S7_MaxSelfDischgRates_48 "电池簇电芯月自放电率最大值";
CM_ SG_ 2332557168 S2A_S7_MinSelfDischgRates_48 "电池簇电芯月自放电率最小值";
CM_ SG_ 2332557168 S2A_S7_AvgSelfDischgRates_48 "电池簇电芯月自放电率平均值";
CM_ SG_ 2332557168 S2A_S7_SOH_48 "平均SOH ";
CM_ SG_ 2332557169 CRC_S2A_S7_49 "S2A概要数据7 的CRC";
CM_ SG_ 2332557169 BAT_SOC_CorrectState_49 "SOC修正状态（最后一次）";
CM_ SG_ 2332557169 Status_of_Closed_Loop "闭环算法开启状态";
CM_ SG_ 2332557169 S2A_S7_FullDisChgFlgFromSBMU_49 "满放标志位";
CM_ SG_ 2332557169 S2A_S7_MaxSelfDischgRates_49 "电池簇电芯月自放电率最大值";
CM_ SG_ 2332557169 S2A_S7_MinSelfDischgRates_49 "电池簇电芯月自放电率最小值";
CM_ SG_ 2332557169 S2A_S7_AvgSelfDischgRates_49 "电池簇电芯月自放电率平均值";
CM_ SG_ 2332557169 S2A_S7_SOH_49 "平均SOH ";
CM_ SG_ 2332557170 CRC_S2A_S7_50 "S2A概要数据7 的CRC";
CM_ SG_ 2332557170 BAT_SOC_CorrectState_50 "SOC修正状态（最后一次）";
CM_ SG_ 2332557170 Status_of_Closed_Loop "闭环算法开启状态";
CM_ SG_ 2332557170 S2A_S7_FullDisChgFlgFromSBMU_50 "满放标志位";
CM_ SG_ 2332557170 S2A_S7_MaxSelfDischgRates_50 "电池簇电芯月自放电率最大值";
CM_ SG_ 2332557170 S2A_S7_MinSelfDischgRates_50 "电池簇电芯月自放电率最小值";
CM_ SG_ 2332557170 S2A_S7_AvgSelfDischgRates_50 "电池簇电芯月自放电率平均值";
CM_ SG_ 2332557170 S2A_S7_SOH_50 "平均SOH ";
CM_ SG_ 2332557171 CRC_S2A_S7_51 "S2A概要数据7 的CRC";
CM_ SG_ 2332557171 BAT_SOC_CorrectState_51 "SOC修正状态（最后一次）";
CM_ SG_ 2332557171 Status_of_Closed_Loop "闭环算法开启状态";
CM_ SG_ 2332557171 S2A_S7_FullDisChgFlgFromSBMU_51 "满放标志位";
CM_ SG_ 2332557171 S2A_S7_MaxSelfDischgRates_51 "电池簇电芯月自放电率最大值";
CM_ SG_ 2332557171 S2A_S7_MinSelfDischgRates_51 "电池簇电芯月自放电率最小值";
CM_ SG_ 2332557171 S2A_S7_AvgSelfDischgRates_51 "电池簇电芯月自放电率平均值";
CM_ SG_ 2332557171 S2A_S7_SOH_51 "平均SOH ";
CM_ SG_ 2332557172 CRC_S2A_S7_52 "S2A概要数据7 的CRC";
CM_ SG_ 2332557172 BAT_SOC_CorrectState_52 "SOC修正状态（最后一次）";
CM_ SG_ 2332557172 Status_of_Closed_Loop "闭环算法开启状态";
CM_ SG_ 2332557172 S2A_S7_FullDisChgFlgFromSBMU_52 "满放标志位";
CM_ SG_ 2332557172 S2A_S7_MaxSelfDischgRates_52 "电池簇电芯月自放电率最大值";
CM_ SG_ 2332557172 S2A_S7_MinSelfDischgRates_52 "电池簇电芯月自放电率最小值";
CM_ SG_ 2332557172 S2A_S7_AvgSelfDischgRates_52 "电池簇电芯月自放电率平均值";
CM_ SG_ 2332557172 S2A_S7_SOH_52 "平均SOH ";
CM_ SG_ 2332557173 CRC_S2A_S7_53 "S2A概要数据7 的CRC";
CM_ SG_ 2332557173 BAT_SOC_CorrectState_53 "SOC修正状态（最后一次）";
CM_ SG_ 2332557173 Status_of_Closed_Loop "闭环算法开启状态";
CM_ SG_ 2332557173 S2A_S7_FullDisChgFlgFromSBMU_53 "满放标志位";
CM_ SG_ 2332557173 S2A_S7_MaxSelfDischgRates_53 "电池簇电芯月自放电率最大值";
CM_ SG_ 2332557173 S2A_S7_MinSelfDischgRates_53 "电池簇电芯月自放电率最小值";
CM_ SG_ 2332557173 S2A_S7_AvgSelfDischgRates_53 "电池簇电芯月自放电率平均值";
CM_ SG_ 2332557173 S2A_S7_SOH_53 "平均SOH ";
CM_ SG_ 2332557174 CRC_S2A_S7_54 "S2A概要数据7 的CRC";
CM_ SG_ 2332557174 BAT_SOC_CorrectState_54 "SOC修正状态（最后一次）";
CM_ SG_ 2332557174 Status_of_Closed_Loop "闭环算法开启状态";
CM_ SG_ 2332557174 S2A_S7_FullDisChgFlgFromSBMU_54 "满放标志位";
CM_ SG_ 2332557174 S2A_S7_MaxSelfDischgRates_54 "电池簇电芯月自放电率最大值";
CM_ SG_ 2332557174 S2A_S7_MinSelfDischgRates_54 "电池簇电芯月自放电率最小值";
CM_ SG_ 2332557174 S2A_S7_AvgSelfDischgRates_54 "电池簇电芯月自放电率平均值";
CM_ SG_ 2332557174 S2A_S7_SOH_54 "平均SOH ";
CM_ SG_ 2332557175 CRC_S2A_S7_55 "S2A概要数据7 的CRC";
CM_ SG_ 2332557175 BAT_SOC_CorrectState_55 "SOC修正状态（最后一次）";
CM_ SG_ 2332557175 Status_of_Closed_Loop "闭环算法开启状态";
CM_ SG_ 2332557175 S2A_S7_FullDisChgFlgFromSBMU_55 "满放标志位";
CM_ SG_ 2332557175 S2A_S7_MaxSelfDischgRates_55 "电池簇电芯月自放电率最大值";
CM_ SG_ 2332557175 S2A_S7_MinSelfDischgRates_55 "电池簇电芯月自放电率最小值";
CM_ SG_ 2332557175 S2A_S7_AvgSelfDischgRates_55 "电池簇电芯月自放电率平均值";
CM_ SG_ 2332557175 S2A_S7_SOH_55 "平均SOH ";
CM_ SG_ 2332557176 CRC_S2A_S7_56 "S2A概要数据7 的CRC";
CM_ SG_ 2332557176 BAT_SOC_CorrectState_56 "SOC修正状态（最后一次）";
CM_ SG_ 2332557176 Status_of_Closed_Loop "闭环算法开启状态";
CM_ SG_ 2332557176 S2A_S7_FullDisChgFlgFromSBMU_56 "满放标志位";
CM_ SG_ 2332557176 S2A_S7_MaxSelfDischgRates_56 "电池簇电芯月自放电率最大值";
CM_ SG_ 2332557176 S2A_S7_MinSelfDischgRates_56 "电池簇电芯月自放电率最小值";
CM_ SG_ 2332557176 S2A_S7_AvgSelfDischgRates_56 "电池簇电芯月自放电率平均值";
CM_ SG_ 2332557176 S2A_S7_SOH_56 "平均SOH ";
CM_ SG_ 2332557177 CRC_S2A_S7_57 "S2A概要数据7 的CRC";
CM_ SG_ 2332557177 BAT_SOC_CorrectState_57 "SOC修正状态（最后一次）";
CM_ SG_ 2332557177 Status_of_Closed_Loop "闭环算法开启状态";
CM_ SG_ 2332557177 S2A_S7_FullDisChgFlgFromSBMU_57 "满放标志位";
CM_ SG_ 2332557177 S2A_S7_MaxSelfDischgRates_57 "电池簇电芯月自放电率最大值";
CM_ SG_ 2332557177 S2A_S7_MinSelfDischgRates_57 "电池簇电芯月自放电率最小值";
CM_ SG_ 2332557177 S2A_S7_AvgSelfDischgRates_57 "电池簇电芯月自放电率平均值";
CM_ SG_ 2332557177 S2A_S7_SOH_57 "平均SOH ";
CM_ SG_ 2332557178 CRC_S2A_S7_58 "S2A概要数据7 的CRC";
CM_ SG_ 2332557178 BAT_SOC_CorrectState_58 "SOC修正状态（最后一次）";
CM_ SG_ 2332557178 Status_of_Closed_Loop "闭环算法开启状态";
CM_ SG_ 2332557178 S2A_S7_FullDisChgFlgFromSBMU_58 "满放标志位";
CM_ SG_ 2332557178 S2A_S7_MaxSelfDischgRates_58 "电池簇电芯月自放电率最大值";
CM_ SG_ 2332557178 S2A_S7_MinSelfDischgRates_58 "电池簇电芯月自放电率最小值";
CM_ SG_ 2332557178 S2A_S7_AvgSelfDischgRates_58 "电池簇电芯月自放电率平均值";
CM_ SG_ 2332557178 S2A_S7_SOH_58 "平均SOH ";
CM_ SG_ 2332557179 CRC_S2A_S7_59 "S2A概要数据7 的CRC";
CM_ SG_ 2332557179 BAT_SOC_CorrectState_59 "SOC修正状态（最后一次）";
CM_ SG_ 2332557179 Status_of_Closed_Loop "闭环算法开启状态";
CM_ SG_ 2332557179 S2A_S7_FullDisChgFlgFromSBMU_59 "满放标志位";
CM_ SG_ 2332557179 S2A_S7_MaxSelfDischgRates_59 "电池簇电芯月自放电率最大值";
CM_ SG_ 2332557179 S2A_S7_MinSelfDischgRates_59 "电池簇电芯月自放电率最小值";
CM_ SG_ 2332557179 S2A_S7_AvgSelfDischgRates_59 "电池簇电芯月自放电率平均值";
CM_ SG_ 2332557179 S2A_S7_SOH_59 "平均SOH ";
CM_ SG_ 2332557180 CRC_S2A_S7_60 "S2A概要数据7 的CRC";
CM_ SG_ 2332557180 BAT_SOC_CorrectState_60 "SOC修正状态（最后一次）";
CM_ SG_ 2332557180 Status_of_Closed_Loop "闭环算法开启状态";
CM_ SG_ 2332557180 S2A_S7_FullDisChgFlgFromSBMU_60 "满放标志位";
CM_ SG_ 2332557180 S2A_S7_MaxSelfDischgRates_60 "电池簇电芯月自放电率最大值";
CM_ SG_ 2332557180 S2A_S7_MinSelfDischgRates_60 "电池簇电芯月自放电率最小值";
CM_ SG_ 2332557180 S2A_S7_AvgSelfDischgRates_60 "电池簇电芯月自放电率平均值";
CM_ SG_ 2332557180 S2A_S7_SOH_60 "平均SOH ";
CM_ SG_ 2332557181 CRC_S2A_S7_61 "S2A概要数据7 的CRC";
CM_ SG_ 2332557181 BAT_SOC_CorrectState_61 "SOC修正状态（最后一次）";
CM_ SG_ 2332557181 Status_of_Closed_Loop "闭环算法开启状态";
CM_ SG_ 2332557181 S2A_S7_FullDisChgFlgFromSBMU_61 "满放标志位";
CM_ SG_ 2332557181 S2A_S7_MaxSelfDischgRates_61 "电池簇电芯月自放电率最大值";
CM_ SG_ 2332557181 S2A_S7_MinSelfDischgRates_61 "电池簇电芯月自放电率最小值";
CM_ SG_ 2332557181 S2A_S7_AvgSelfDischgRates_61 "电池簇电芯月自放电率平均值";
CM_ SG_ 2332557181 S2A_S7_SOH_61 "平均SOH ";
CM_ SG_ 2332557182 CRC_S2A_S7_62 "S2A概要数据7 的CRC";
CM_ SG_ 2332557182 BAT_SOC_CorrectState_62 "SOC修正状态（最后一次）";
CM_ SG_ 2332557182 Status_of_Closed_Loop "闭环算法开启状态";
CM_ SG_ 2332557182 S2A_S7_FullDisChgFlgFromSBMU_62 "满放标志位";
CM_ SG_ 2332557182 S2A_S7_MaxSelfDischgRates_62 "电池簇电芯月自放电率最大值";
CM_ SG_ 2332557182 S2A_S7_MinSelfDischgRates_62 "电池簇电芯月自放电率最小值";
CM_ SG_ 2332557182 S2A_S7_AvgSelfDischgRates_62 "电池簇电芯月自放电率平均值";
CM_ SG_ 2332557182 S2A_S7_SOH_62 "平均SOH ";
CM_ SG_ 2332557183 CRC_S2A_S7_63 "S2A概要数据7 的CRC";
CM_ SG_ 2332557183 BAT_SOC_CorrectState_63 "SOC修正状态（最后一次）";
CM_ SG_ 2332557183 Status_of_Closed_Loop "闭环算法开启状态";
CM_ SG_ 2332557183 S2A_S7_FullDisChgFlgFromSBMU_63 "满放标志位";
CM_ SG_ 2332557183 S2A_S7_MaxSelfDischgRates_63 "电池簇电芯月自放电率最大值";
CM_ SG_ 2332557183 S2A_S7_MinSelfDischgRates_63 "电池簇电芯月自放电率最小值";
CM_ SG_ 2332557183 S2A_S7_AvgSelfDischgRates_63 "电池簇电芯月自放电率平均值";
CM_ SG_ 2332557183 S2A_S7_SOH_63 "平均SOH ";
CM_ SG_ 2332622657 S2A_HIS_Charge_Engery_01 "历史充电能量 /新增历史充电容量 
2022/10/27已新增 ";
CM_ SG_ 2332622657 S2A_HIS_Discharge_Engery_01 "历史放电能量 /新增历史放电容量
2022/10/27已新增 ";
CM_ SG_ 2332622658 S2A_HIS_Charge_Engery_02 "历史充电能量 /新增历史充电容量 
2022/10/27已新增 ";
CM_ SG_ 2332622658 S2A_HIS_Discharge_Engery_02 "历史放电能量 /新增历史放电容量
2022/10/27已新增 ";
CM_ SG_ 2332622659 S2A_HIS_Charge_Engery_03 "历史充电能量 /新增历史充电容量 
2022/10/27已新增 ";
CM_ SG_ 2332622659 S2A_HIS_Discharge_Engery_03 "历史放电能量 /新增历史放电容量
2022/10/27已新增 ";
CM_ SG_ 2332622660 S2A_HIS_Charge_Engery_04 "历史充电能量 /新增历史充电容量 
2022/10/27已新增 ";
CM_ SG_ 2332622660 S2A_HIS_Discharge_Engery_04 "历史放电能量 /新增历史放电容量
2022/10/27已新增 ";
CM_ SG_ 2332622661 S2A_HIS_Charge_Engery_05 "历史充电能量 /新增历史充电容量 
2022/10/27已新增 ";
CM_ SG_ 2332622661 S2A_HIS_Discharge_Engery_05 "历史放电能量 /新增历史放电容量
2022/10/27已新增 ";
CM_ SG_ 2332622662 S2A_HIS_Charge_Engery_06 "历史充电能量 /新增历史充电容量 
2022/10/27已新增 ";
CM_ SG_ 2332622662 S2A_HIS_Discharge_Engery_06 "历史放电能量 /新增历史放电容量
2022/10/27已新增 ";
CM_ SG_ 2332622663 S2A_HIS_Charge_Engery_07 "历史充电能量 /新增历史充电容量 
2022/10/27已新增 ";
CM_ SG_ 2332622663 S2A_HIS_Discharge_Engery_07 "历史放电能量 /新增历史放电容量
2022/10/27已新增 ";
CM_ SG_ 2332622664 S2A_HIS_Charge_Engery_08 "历史充电能量 /新增历史充电容量 
2022/10/27已新增 ";
CM_ SG_ 2332622664 S2A_HIS_Discharge_Engery_08 "历史放电能量 /新增历史放电容量
2022/10/27已新增 ";
CM_ SG_ 2332622665 S2A_HIS_Charge_Engery_09 "历史充电能量 /新增历史充电容量 
2022/10/27已新增 ";
CM_ SG_ 2332622665 S2A_HIS_Discharge_Engery_09 "历史放电能量 /新增历史放电容量
2022/10/27已新增 ";
CM_ SG_ 2332622666 S2A_HIS_Charge_Engery_10 "历史充电能量 /新增历史充电容量 
2022/10/27已新增 ";
CM_ SG_ 2332622666 S2A_HIS_Discharge_Engery_10 "历史放电能量 /新增历史放电容量
2022/10/27已新增 ";
CM_ SG_ 2332622667 S2A_HIS_Charge_Engery_11 "历史充电能量 /新增历史充电容量 
2022/10/27已新增 ";
CM_ SG_ 2332622667 S2A_HIS_Discharge_Engery_11 "历史放电能量 /新增历史放电容量
2022/10/27已新增 ";
CM_ SG_ 2332622668 S2A_HIS_Charge_Engery_12 "历史充电能量 /新增历史充电容量 
2022/10/27已新增 ";
CM_ SG_ 2332622668 S2A_HIS_Discharge_Engery_12 "历史放电能量 /新增历史放电容量
2022/10/27已新增 ";
CM_ SG_ 2332622669 S2A_HIS_Charge_Engery_13 "历史充电能量 /新增历史充电容量 
2022/10/27已新增 ";
CM_ SG_ 2332622669 S2A_HIS_Discharge_Engery_13 "历史放电能量 /新增历史放电容量
2022/10/27已新增 ";
CM_ SG_ 2332622670 S2A_HIS_Charge_Engery_14 "历史充电能量 /新增历史充电容量 
2022/10/27已新增 ";
CM_ SG_ 2332622670 S2A_HIS_Discharge_Engery_14 "历史放电能量 /新增历史放电容量
2022/10/27已新增 ";
CM_ SG_ 2332622671 S2A_HIS_Charge_Engery_15 "历史充电能量 /新增历史充电容量 
2022/10/27已新增 ";
CM_ SG_ 2332622671 S2A_HIS_Discharge_Engery_15 "历史放电能量 /新增历史放电容量
2022/10/27已新增 ";
CM_ SG_ 2332622672 S2A_HIS_Charge_Engery_16 "历史充电能量 /新增历史充电容量 
2022/10/27已新增 ";
CM_ SG_ 2332622672 S2A_HIS_Discharge_Engery_16 "历史放电能量 /新增历史放电容量
2022/10/27已新增 ";
CM_ SG_ 2332622673 S2A_HIS_Charge_Engery_17 "历史充电能量 /新增历史充电容量 
2022/10/27已新增 ";
CM_ SG_ 2332622673 S2A_HIS_Discharge_Engery_17 "历史放电能量 /新增历史放电容量
2022/10/27已新增 ";
CM_ SG_ 2332622674 S2A_HIS_Charge_Engery_18 "历史充电能量 /新增历史充电容量 
2022/10/27已新增 ";
CM_ SG_ 2332622674 S2A_HIS_Discharge_Engery_18 "历史放电能量 /新增历史放电容量
2022/10/27已新增 ";
CM_ SG_ 2332622675 S2A_HIS_Charge_Engery_19 "历史充电能量 /新增历史充电容量 
2022/10/27已新增 ";
CM_ SG_ 2332622675 S2A_HIS_Discharge_Engery_19 "历史放电能量 /新增历史放电容量
2022/10/27已新增 ";
CM_ SG_ 2332622676 S2A_HIS_Charge_Engery_20 "历史充电能量 /新增历史充电容量 
2022/10/27已新增 ";
CM_ SG_ 2332622676 S2A_HIS_Discharge_Engery_20 "历史放电能量 /新增历史放电容量
2022/10/27已新增 ";
CM_ SG_ 2332622677 S2A_HIS_Charge_Engery_21 "历史充电能量 /新增历史充电容量 
2022/10/27已新增 ";
CM_ SG_ 2332622677 S2A_HIS_Discharge_Engery_21 "历史放电能量 /新增历史放电容量
2022/10/27已新增 ";
CM_ SG_ 2332622678 S2A_HIS_Charge_Engery_22 "历史充电能量 /新增历史充电容量 
2022/10/27已新增 ";
CM_ SG_ 2332622678 S2A_HIS_Discharge_Engery_22 "历史放电能量 /新增历史放电容量
2022/10/27已新增 ";
CM_ SG_ 2332622679 S2A_HIS_Charge_Engery_23 "历史充电能量 /新增历史充电容量 
2022/10/27已新增 ";
CM_ SG_ 2332622679 S2A_HIS_Discharge_Engery_23 "历史放电能量 /新增历史放电容量
2022/10/27已新增 ";
CM_ SG_ 2332622680 S2A_HIS_Charge_Engery_24 "历史充电能量 /新增历史充电容量 
2022/10/27已新增 ";
CM_ SG_ 2332622680 S2A_HIS_Discharge_Engery_24 "历史放电能量 /新增历史放电容量
2022/10/27已新增 ";
CM_ SG_ 2332622681 S2A_HIS_Charge_Engery_25 "历史充电能量 /新增历史充电容量 
2022/10/27已新增 ";
CM_ SG_ 2332622681 S2A_HIS_Discharge_Engery_25 "历史放电能量 /新增历史放电容量
2022/10/27已新增 ";
CM_ SG_ 2332622682 S2A_HIS_Charge_Engery_26 "历史充电能量 /新增历史充电容量 
2022/10/27已新增 ";
CM_ SG_ 2332622682 S2A_HIS_Discharge_Engery_26 "历史放电能量 /新增历史放电容量
2022/10/27已新增 ";
CM_ SG_ 2332622683 S2A_HIS_Charge_Engery_27 "历史充电能量 /新增历史充电容量 
2022/10/27已新增 ";
CM_ SG_ 2332622683 S2A_HIS_Discharge_Engery_27 "历史放电能量 /新增历史放电容量
2022/10/27已新增 ";
CM_ SG_ 2332622684 S2A_HIS_Charge_Engery_28 "历史充电能量 /新增历史充电容量 
2022/10/27已新增 ";
CM_ SG_ 2332622684 S2A_HIS_Discharge_Engery_28 "历史放电能量 /新增历史放电容量
2022/10/27已新增 ";
CM_ SG_ 2332622685 S2A_HIS_Charge_Engery_29 "历史充电能量 /新增历史充电容量 
2022/10/27已新增 ";
CM_ SG_ 2332622685 S2A_HIS_Discharge_Engery_29 "历史放电能量 /新增历史放电容量
2022/10/27已新增 ";
CM_ SG_ 2332622686 S2A_HIS_Charge_Engery_30 "历史充电能量 /新增历史充电容量 
2022/10/27已新增 ";
CM_ SG_ 2332622686 S2A_HIS_Discharge_Engery_30 "历史放电能量 /新增历史放电容量
2022/10/27已新增 ";
CM_ SG_ 2332622687 S2A_HIS_Charge_Engery_31 "历史充电能量 /新增历史充电容量 
2022/10/27已新增 ";
CM_ SG_ 2332622687 S2A_HIS_Discharge_Engery_31 "历史放电能量 /新增历史放电容量
2022/10/27已新增 ";
CM_ SG_ 2332622688 S2A_HIS_Charge_Engery_32 "历史充电能量 /新增历史充电容量 
2022/10/27已新增 ";
CM_ SG_ 2332622688 S2A_HIS_Discharge_Engery_32 "历史放电能量 /新增历史放电容量
2022/10/27已新增 ";
CM_ SG_ 2332622689 S2A_HIS_Charge_Engery_33 "历史充电能量 /新增历史充电容量 
2022/10/27已新增 ";
CM_ SG_ 2332622689 S2A_HIS_Discharge_Engery_33 "历史放电能量 /新增历史放电容量
2022/10/27已新增 ";
CM_ SG_ 2332622690 S2A_HIS_Charge_Engery_34 "历史充电能量 /新增历史充电容量 
2022/10/27已新增 ";
CM_ SG_ 2332622690 S2A_HIS_Discharge_Engery_34 "历史放电能量 /新增历史放电容量
2022/10/27已新增 ";
CM_ SG_ 2332622691 S2A_HIS_Charge_Engery_35 "历史充电能量 /新增历史充电容量 
2022/10/27已新增 ";
CM_ SG_ 2332622691 S2A_HIS_Discharge_Engery_35 "历史放电能量 /新增历史放电容量
2022/10/27已新增 ";
CM_ SG_ 2332622692 S2A_HIS_Charge_Engery_36 "历史充电能量 /新增历史充电容量 
2022/10/27已新增 ";
CM_ SG_ 2332622692 S2A_HIS_Discharge_Engery_36 "历史放电能量 /新增历史放电容量
2022/10/27已新增 ";
CM_ SG_ 2332622693 S2A_HIS_Charge_Engery_37 "历史充电能量 /新增历史充电容量 
2022/10/27已新增 ";
CM_ SG_ 2332622693 S2A_HIS_Discharge_Engery_37 "历史放电能量 /新增历史放电容量
2022/10/27已新增 ";
CM_ SG_ 2332622694 S2A_HIS_Charge_Engery_38 "历史充电能量 /新增历史充电容量 
2022/10/27已新增 ";
CM_ SG_ 2332622694 S2A_HIS_Discharge_Engery_38 "历史放电能量 /新增历史放电容量
2022/10/27已新增 ";
CM_ SG_ 2332622695 S2A_HIS_Charge_Engery_39 "历史充电能量 /新增历史充电容量 
2022/10/27已新增 ";
CM_ SG_ 2332622695 S2A_HIS_Discharge_Engery_39 "历史放电能量 /新增历史放电容量
2022/10/27已新增 ";
CM_ SG_ 2332622696 S2A_HIS_Charge_Engery_40 "历史充电能量 /新增历史充电容量 
2022/10/27已新增 ";
CM_ SG_ 2332622696 S2A_HIS_Discharge_Engery_40 "历史放电能量 /新增历史放电容量
2022/10/27已新增 ";
CM_ SG_ 2332622697 S2A_HIS_Charge_Engery_41 "历史充电能量 /新增历史充电容量 
2022/10/27已新增 ";
CM_ SG_ 2332622697 S2A_HIS_Discharge_Engery_41 "历史放电能量 /新增历史放电容量
2022/10/27已新增 ";
CM_ SG_ 2332622698 S2A_HIS_Charge_Engery_42 "历史充电能量 /新增历史充电容量 
2022/10/27已新增 ";
CM_ SG_ 2332622698 S2A_HIS_Discharge_Engery_42 "历史放电能量 /新增历史放电容量
2022/10/27已新增 ";
CM_ SG_ 2332622699 S2A_HIS_Charge_Engery_43 "历史充电能量 /新增历史充电容量 
2022/10/27已新增 ";
CM_ SG_ 2332622699 S2A_HIS_Discharge_Engery_43 "历史放电能量 /新增历史放电容量
2022/10/27已新增 ";
CM_ SG_ 2332622700 S2A_HIS_Charge_Engery_44 "历史充电能量 /新增历史充电容量 
2022/10/27已新增 ";
CM_ SG_ 2332622700 S2A_HIS_Discharge_Engery_44 "历史放电能量 /新增历史放电容量
2022/10/27已新增 ";
CM_ SG_ 2332622701 S2A_HIS_Charge_Engery_45 "历史充电能量 /新增历史充电容量 
2022/10/27已新增 ";
CM_ SG_ 2332622701 S2A_HIS_Discharge_Engery_45 "历史放电能量 /新增历史放电容量
2022/10/27已新增 ";
CM_ SG_ 2332622702 S2A_HIS_Charge_Engery_46 "历史充电能量 /新增历史充电容量 
2022/10/27已新增 ";
CM_ SG_ 2332622702 S2A_HIS_Discharge_Engery_46 "历史放电能量 /新增历史放电容量
2022/10/27已新增 ";
CM_ SG_ 2332622703 S2A_HIS_Charge_Engery_47 "历史充电能量 /新增历史充电容量 
2022/10/27已新增 ";
CM_ SG_ 2332622703 S2A_HIS_Discharge_Engery_47 "历史放电能量 /新增历史放电容量
2022/10/27已新增 ";
CM_ SG_ 2332622704 S2A_HIS_Charge_Engery_48 "历史充电能量 /新增历史充电容量 
2022/10/27已新增 ";
CM_ SG_ 2332622704 S2A_HIS_Discharge_Engery_48 "历史放电能量 /新增历史放电容量
2022/10/27已新增 ";
CM_ SG_ 2332622705 S2A_HIS_Charge_Engery_49 "历史充电能量 /新增历史充电容量 
2022/10/27已新增 ";
CM_ SG_ 2332622705 S2A_HIS_Discharge_Engery_49 "历史放电能量 /新增历史放电容量
2022/10/27已新增 ";
CM_ SG_ 2332622706 S2A_HIS_Charge_Engery_50 "历史充电能量 /新增历史充电容量 
2022/10/27已新增 ";
CM_ SG_ 2332622706 S2A_HIS_Discharge_Engery_50 "历史放电能量 /新增历史放电容量
2022/10/27已新增 ";
CM_ SG_ 2332622707 S2A_HIS_Charge_Engery_51 "历史充电能量 /新增历史充电容量 
2022/10/27已新增 ";
CM_ SG_ 2332622707 S2A_HIS_Discharge_Engery_51 "历史放电能量 /新增历史放电容量
2022/10/27已新增 ";
CM_ SG_ 2332622708 S2A_HIS_Charge_Engery_52 "历史充电能量 /新增历史充电容量 
2022/10/27已新增 ";
CM_ SG_ 2332622708 S2A_HIS_Discharge_Engery_52 "历史放电能量 /新增历史放电容量
2022/10/27已新增 ";
CM_ SG_ 2332622709 S2A_HIS_Charge_Engery_53 "历史充电能量 /新增历史充电容量 
2022/10/27已新增 ";
CM_ SG_ 2332622709 S2A_HIS_Discharge_Engery_53 "历史放电能量 /新增历史放电容量
2022/10/27已新增 ";
CM_ SG_ 2332622710 S2A_HIS_Charge_Engery_54 "历史充电能量 /新增历史充电容量 
2022/10/27已新增 ";
CM_ SG_ 2332622710 S2A_HIS_Discharge_Engery_54 "历史放电能量 /新增历史放电容量
2022/10/27已新增 ";
CM_ SG_ 2332622711 S2A_HIS_Charge_Engery_55 "历史充电能量 /新增历史充电容量 
2022/10/27已新增 ";
CM_ SG_ 2332622711 S2A_HIS_Discharge_Engery_55 "历史放电能量 /新增历史放电容量
2022/10/27已新增 ";
CM_ SG_ 2332622712 S2A_HIS_Charge_Engery_56 "历史充电能量 /新增历史充电容量 
2022/10/27已新增 ";
CM_ SG_ 2332622712 S2A_HIS_Discharge_Engery_56 "历史放电能量 /新增历史放电容量
2022/10/27已新增 ";
CM_ SG_ 2332622713 S2A_HIS_Charge_Engery_57 "历史充电能量 /新增历史充电容量 
2022/10/27已新增 ";
CM_ SG_ 2332622713 S2A_HIS_Discharge_Engery_57 "历史放电能量 /新增历史放电容量
2022/10/27已新增 ";
CM_ SG_ 2332622714 S2A_HIS_Charge_Engery_58 "历史充电能量 /新增历史充电容量 
2022/10/27已新增 ";
CM_ SG_ 2332622714 S2A_HIS_Discharge_Engery_58 "历史放电能量 /新增历史放电容量
2022/10/27已新增 ";
CM_ SG_ 2332622715 S2A_HIS_Charge_Engery_59 "历史充电能量 /新增历史充电容量 
2022/10/27已新增 ";
CM_ SG_ 2332622715 S2A_HIS_Discharge_Engery_59 "历史放电能量 /新增历史放电容量
2022/10/27已新增 ";
CM_ SG_ 2332622716 S2A_HIS_Charge_Engery_60 "历史充电能量 /新增历史充电容量 
2022/10/27已新增 ";
CM_ SG_ 2332622716 S2A_HIS_Discharge_Engery_60 "历史放电能量 /新增历史放电容量
2022/10/27已新增 ";
CM_ SG_ 2332622717 S2A_HIS_Charge_Engery_61 "历史充电能量 /新增历史充电容量 
2022/10/27已新增 ";
CM_ SG_ 2332622717 S2A_HIS_Discharge_Engery_61 "历史放电能量 /新增历史放电容量
2022/10/27已新增 ";
CM_ SG_ 2332622718 S2A_HIS_Charge_Engery_62 "历史充电能量 /新增历史充电容量 
2022/10/27已新增 ";
CM_ SG_ 2332622718 S2A_HIS_Discharge_Engery_62 "历史放电能量 /新增历史放电容量
2022/10/27已新增 ";
CM_ SG_ 2332622719 S2A_HIS_Charge_Engery_63 "历史充电能量 /新增历史充电容量 
2022/10/27已新增 ";
CM_ SG_ 2332622719 S2A_HIS_Discharge_Engery_63 "历史放电能量 /新增历史放电容量
2022/10/27已新增 ";
CM_ SG_ 2332819265 S2A_LookUpTblCurr_01 "充电查表电流";
CM_ SG_ 2332819265 S2A_NominalCellVol01 "·";
CM_ SG_ 2332819265 S2A_Limit_CellChargeVol_01 "电芯单体充电限制电压";
CM_ SG_ 2332819265 S2A_Limit_CellDisChargeVol_01 "电芯单体放电限制电压";
CM_ SG_ 2332819265 S2A_Num_CellVoltSensors_Rack01 "支路上的电芯电压传感器数量 ";
CM_ SG_ 2332819266 S2A_LookUpTblCurr_02 "充电查表电流";
CM_ SG_ 2332819266 S2A_NominalCellVol02 "·";
CM_ SG_ 2332819266 S2A_Limit_CellChargeVol_02 "电芯单体充电限制电压";
CM_ SG_ 2332819266 S2A_Limit_CellDisChargeVol_02 "电芯单体放电限制电压";
CM_ SG_ 2332819266 S2A_Num_CellVoltSensors_Rack02 "支路上的电芯电压传感器数量 ";
CM_ SG_ 2332819267 S2A_LookUpTblCurr_03 "充电查表电流";
CM_ SG_ 2332819267 S2A_NominalCellVol03 "·";
CM_ SG_ 2332819267 S2A_Limit_CellChargeVol_03 "电芯单体充电限制电压";
CM_ SG_ 2332819267 S2A_Limit_CellDisChargeVol_03 "电芯单体放电限制电压";
CM_ SG_ 2332819267 S2A_Num_CellVoltSensors_Rack03 "支路上的电芯电压传感器数量 ";
CM_ SG_ 2332819268 S2A_LookUpTblCurr_04 "充电查表电流";
CM_ SG_ 2332819268 S2A_NominalCellVol04 "·";
CM_ SG_ 2332819268 S2A_Limit_CellChargeVol_04 "电芯单体充电限制电压";
CM_ SG_ 2332819268 S2A_Limit_CellDisChargeVol_04 "电芯单体放电限制电压";
CM_ SG_ 2332819268 S2A_Num_CellVoltSensors_Rack04 "支路上的电芯电压传感器数量 ";
CM_ SG_ 2332819269 S2A_LookUpTblCurr_05 "充电查表电流";
CM_ SG_ 2332819269 S2A_NominalCellVol05 "·";
CM_ SG_ 2332819269 S2A_Limit_CellChargeVol_05 "电芯单体充电限制电压";
CM_ SG_ 2332819269 S2A_Limit_CellDisChargeVol_05 "电芯单体放电限制电压";
CM_ SG_ 2332819269 S2A_Num_CellVoltSensors_Rack05 "支路上的电芯电压传感器数量 ";
CM_ SG_ 2332819270 S2A_LookUpTblCurr_06 "充电查表电流";
CM_ SG_ 2332819270 S2A_NominalCellVol06 "·";
CM_ SG_ 2332819270 S2A_Limit_CellChargeVol_06 "电芯单体充电限制电压";
CM_ SG_ 2332819270 S2A_Limit_CellDisChargeVol_06 "电芯单体放电限制电压";
CM_ SG_ 2332819270 S2A_Num_CellVoltSensors_Rack06 "支路上的电芯电压传感器数量 ";
CM_ SG_ 2332819271 S2A_LookUpTblCurr_07 "充电查表电流";
CM_ SG_ 2332819271 S2A_NominalCellVol07 "·";
CM_ SG_ 2332819271 S2A_Limit_CellChargeVol_07 "电芯单体充电限制电压";
CM_ SG_ 2332819271 S2A_Limit_CellDisChargeVol_07 "电芯单体放电限制电压";
CM_ SG_ 2332819271 S2A_Num_CellVoltSensors_Rack07 "支路上的电芯电压传感器数量 ";
CM_ SG_ 2332819272 S2A_LookUpTblCurr_08 "充电查表电流";
CM_ SG_ 2332819272 S2A_NominalCellVol08 "·";
CM_ SG_ 2332819272 S2A_Limit_CellChargeVol_08 "电芯单体充电限制电压";
CM_ SG_ 2332819272 S2A_Limit_CellDisChargeVol_08 "电芯单体放电限制电压";
CM_ SG_ 2332819272 S2A_Num_CellVoltSensors_Rack08 "支路上的电芯电压传感器数量 ";
CM_ SG_ 2332819273 S2A_LookUpTblCurr_09 "充电查表电流";
CM_ SG_ 2332819273 S2A_NominalCellVol09 "·";
CM_ SG_ 2332819273 S2A_Limit_CellChargeVol_09 "电芯单体充电限制电压";
CM_ SG_ 2332819273 S2A_Limit_CellDisChargeVol_09 "电芯单体放电限制电压";
CM_ SG_ 2332819273 S2A_Num_CellVoltSensors_Rack09 "支路上的电芯电压传感器数量 ";
CM_ SG_ 2332819274 S2A_LookUpTblCurr_10 "充电查表电流";
CM_ SG_ 2332819274 S2A_NominalCellVol10 "·";
CM_ SG_ 2332819274 S2A_Limit_CellChargeVol_10 "电芯单体充电限制电压";
CM_ SG_ 2332819274 S2A_Limit_CellDisChargeVol_10 "电芯单体放电限制电压";
CM_ SG_ 2332819274 S2A_Num_CellVoltSensors_Rack10 "支路上的电芯电压传感器数量 ";
CM_ SG_ 2332819275 S2A_LookUpTblCurr_11 "充电查表电流";
CM_ SG_ 2332819275 S2A_NominalCellVol11 "·";
CM_ SG_ 2332819275 S2A_Limit_CellChargeVol_11 "电芯单体充电限制电压";
CM_ SG_ 2332819275 S2A_Limit_CellDisChargeVol_11 "电芯单体放电限制电压";
CM_ SG_ 2332819275 S2A_Num_CellVoltSensors_Rack11 "支路上的电芯电压传感器数量 ";
CM_ SG_ 2332819276 S2A_LookUpTblCurr_12 "充电查表电流";
CM_ SG_ 2332819276 S2A_NominalCellVol12 "·";
CM_ SG_ 2332819276 S2A_Limit_CellChargeVol_12 "电芯单体充电限制电压";
CM_ SG_ 2332819276 S2A_Limit_CellDisChargeVol_12 "电芯单体放电限制电压";
CM_ SG_ 2332819276 S2A_Num_CellVoltSensors_Rack12 "支路上的电芯电压传感器数量 ";
CM_ SG_ 2332819277 S2A_LookUpTblCurr_13 "充电查表电流";
CM_ SG_ 2332819277 S2A_NominalCellVol13 "·";
CM_ SG_ 2332819277 S2A_Limit_CellChargeVol_13 "电芯单体充电限制电压";
CM_ SG_ 2332819277 S2A_Limit_CellDisChargeVol_13 "电芯单体放电限制电压";
CM_ SG_ 2332819277 S2A_Num_CellVoltSensors_Rack13 "支路上的电芯电压传感器数量 ";
CM_ SG_ 2332819278 S2A_LookUpTblCurr_14 "充电查表电流";
CM_ SG_ 2332819278 S2A_NominalCellVol14 "·";
CM_ SG_ 2332819278 S2A_Limit_CellChargeVol_14 "电芯单体充电限制电压";
CM_ SG_ 2332819278 S2A_Limit_CellDisChargeVol_14 "电芯单体放电限制电压";
CM_ SG_ 2332819278 S2A_Num_CellVoltSensors_Rack14 "支路上的电芯电压传感器数量 ";
CM_ SG_ 2332819279 S2A_LookUpTblCurr_15 "充电查表电流";
CM_ SG_ 2332819279 S2A_NominalCellVol15 "·";
CM_ SG_ 2332819279 S2A_Limit_CellChargeVol_15 "电芯单体充电限制电压";
CM_ SG_ 2332819279 S2A_Limit_CellDisChargeVol_15 "电芯单体放电限制电压";
CM_ SG_ 2332819279 S2A_Num_CellVoltSensors_Rack15 "支路上的电芯电压传感器数量 ";
CM_ SG_ 2332819280 S2A_LookUpTblCurr_16 "充电查表电流";
CM_ SG_ 2332819280 S2A_NominalCellVol16 "·";
CM_ SG_ 2332819280 S2A_Limit_CellChargeVol_16 "电芯单体充电限制电压";
CM_ SG_ 2332819280 S2A_Limit_CellDisChargeVol_16 "电芯单体放电限制电压";
CM_ SG_ 2332819280 S2A_Num_CellVoltSensors_Rack16 "支路上的电芯电压传感器数量 ";
CM_ SG_ 2332819281 S2A_LookUpTblCurr_17 "充电查表电流";
CM_ SG_ 2332819281 S2A_NominalCellVol17 "·";
CM_ SG_ 2332819281 S2A_Limit_CellChargeVol_17 "电芯单体充电限制电压";
CM_ SG_ 2332819281 S2A_Limit_CellDisChargeVol_17 "电芯单体放电限制电压";
CM_ SG_ 2332819281 S2A_Num_CellVoltSensors_Rack17 "支路上的电芯电压传感器数量 ";
CM_ SG_ 2332819282 S2A_LookUpTblCurr_18 "充电查表电流";
CM_ SG_ 2332819282 S2A_NominalCellVol18 "·";
CM_ SG_ 2332819282 S2A_Limit_CellChargeVol_18 "电芯单体充电限制电压";
CM_ SG_ 2332819282 S2A_Limit_CellDisChargeVol_18 "电芯单体放电限制电压";
CM_ SG_ 2332819282 S2A_Num_CellVoltSensors_Rack18 "支路上的电芯电压传感器数量 ";
CM_ SG_ 2332819283 S2A_LookUpTblCurr_19 "充电查表电流";
CM_ SG_ 2332819283 S2A_NominalCellVol19 "·";
CM_ SG_ 2332819283 S2A_Limit_CellChargeVol_19 "电芯单体充电限制电压";
CM_ SG_ 2332819283 S2A_Limit_CellDisChargeVol_19 "电芯单体放电限制电压";
CM_ SG_ 2332819283 S2A_Num_CellVoltSensors_Rack19 "支路上的电芯电压传感器数量 ";
CM_ SG_ 2332819284 S2A_LookUpTblCurr_20 "充电查表电流";
CM_ SG_ 2332819284 S2A_NominalCellVol20 "·";
CM_ SG_ 2332819284 S2A_Limit_CellChargeVol_20 "电芯单体充电限制电压";
CM_ SG_ 2332819284 S2A_Limit_CellDisChargeVol_20 "电芯单体放电限制电压";
CM_ SG_ 2332819284 S2A_Num_CellVoltSensors_Rack20 "支路上的电芯电压传感器数量 ";
CM_ SG_ 2332819285 S2A_LookUpTblCurr_21 "充电查表电流";
CM_ SG_ 2332819285 S2A_NominalCellVol21 "·";
CM_ SG_ 2332819285 S2A_Limit_CellChargeVol_21 "电芯单体充电限制电压";
CM_ SG_ 2332819285 S2A_Limit_CellDisChargeVol_21 "电芯单体放电限制电压";
CM_ SG_ 2332819285 S2A_Num_CellVoltSensors_Rack21 "支路上的电芯电压传感器数量 ";
CM_ SG_ 2332819286 S2A_LookUpTblCurr_22 "充电查表电流";
CM_ SG_ 2332819286 S2A_NominalCellVol22 "·";
CM_ SG_ 2332819286 S2A_Limit_CellChargeVol_22 "电芯单体充电限制电压";
CM_ SG_ 2332819286 S2A_Limit_CellDisChargeVol_22 "电芯单体放电限制电压";
CM_ SG_ 2332819286 S2A_Num_CellVoltSensors_Rack22 "支路上的电芯电压传感器数量 ";
CM_ SG_ 2332819287 S2A_LookUpTblCurr_23 "充电查表电流";
CM_ SG_ 2332819287 S2A_NominalCellVol23 "·";
CM_ SG_ 2332819287 S2A_Limit_CellChargeVol_23 "电芯单体充电限制电压";
CM_ SG_ 2332819287 S2A_Limit_CellDisChargeVol_23 "电芯单体放电限制电压";
CM_ SG_ 2332819287 S2A_Num_CellVoltSensors_Rack23 "支路上的电芯电压传感器数量 ";
CM_ SG_ 2332819288 S2A_LookUpTblCurr_24 "充电查表电流";
CM_ SG_ 2332819288 S2A_NominalCellVol24 "·";
CM_ SG_ 2332819288 S2A_Limit_CellChargeVol_24 "电芯单体充电限制电压";
CM_ SG_ 2332819288 S2A_Limit_CellDisChargeVol_24 "电芯单体放电限制电压";
CM_ SG_ 2332819288 S2A_Num_CellVoltSensors_Rack24 "支路上的电芯电压传感器数量 ";
CM_ SG_ 2332819289 S2A_LookUpTblCurr_25 "充电查表电流";
CM_ SG_ 2332819289 S2A_NominalCellVol25 "·";
CM_ SG_ 2332819289 S2A_Limit_CellChargeVol_25 "电芯单体充电限制电压";
CM_ SG_ 2332819289 S2A_Limit_CellDisChargeVol_25 "电芯单体放电限制电压";
CM_ SG_ 2332819289 S2A_Num_CellVoltSensors_Rack25 "支路上的电芯电压传感器数量 ";
CM_ SG_ 2332819290 S2A_LookUpTblCurr_26 "充电查表电流";
CM_ SG_ 2332819290 S2A_NominalCellVol26 "·";
CM_ SG_ 2332819290 S2A_Limit_CellChargeVol_26 "电芯单体充电限制电压";
CM_ SG_ 2332819290 S2A_Limit_CellDisChargeVol_26 "电芯单体放电限制电压";
CM_ SG_ 2332819290 S2A_Num_CellVoltSensors_Rack26 "支路上的电芯电压传感器数量 ";
CM_ SG_ 2332819291 S2A_LookUpTblCurr_27 "充电查表电流";
CM_ SG_ 2332819291 S2A_NominalCellVol27 "·";
CM_ SG_ 2332819291 S2A_Limit_CellChargeVol_27 "电芯单体充电限制电压";
CM_ SG_ 2332819291 S2A_Limit_CellDisChargeVol_27 "电芯单体放电限制电压";
CM_ SG_ 2332819291 S2A_Num_CellVoltSensors_Rack27 "支路上的电芯电压传感器数量 ";
CM_ SG_ 2332819292 S2A_LookUpTblCurr_28 "充电查表电流";
CM_ SG_ 2332819292 S2A_NominalCellVol28 "·";
CM_ SG_ 2332819292 S2A_Limit_CellChargeVol_28 "电芯单体充电限制电压";
CM_ SG_ 2332819292 S2A_Limit_CellDisChargeVol_28 "电芯单体放电限制电压";
CM_ SG_ 2332819292 S2A_Num_CellVoltSensors_Rack28 "支路上的电芯电压传感器数量 ";
CM_ SG_ 2332819293 S2A_LookUpTblCurr_29 "充电查表电流";
CM_ SG_ 2332819293 S2A_NominalCellVol29 "·";
CM_ SG_ 2332819293 S2A_Limit_CellChargeVol_29 "电芯单体充电限制电压";
CM_ SG_ 2332819293 S2A_Limit_CellDisChargeVol_29 "电芯单体放电限制电压";
CM_ SG_ 2332819293 S2A_Num_CellVoltSensors_Rack29 "支路上的电芯电压传感器数量 ";
CM_ SG_ 2332819294 S2A_LookUpTblCurr_30 "充电查表电流";
CM_ SG_ 2332819294 S2A_NominalCellVol30 "·";
CM_ SG_ 2332819294 S2A_Limit_CellChargeVol_30 "电芯单体充电限制电压";
CM_ SG_ 2332819294 S2A_Limit_CellDisChargeVol_30 "电芯单体放电限制电压";
CM_ SG_ 2332819294 S2A_Num_CellVoltSensors_Rack30 "支路上的电芯电压传感器数量 ";
CM_ SG_ 2332819295 S2A_LookUpTblCurr_31 "充电查表电流";
CM_ SG_ 2332819295 S2A_NominalCellVol31 "·";
CM_ SG_ 2332819295 S2A_Limit_CellChargeVol_31 "电芯单体充电限制电压";
CM_ SG_ 2332819295 S2A_Limit_CellDisChargeVol_31 "电芯单体放电限制电压";
CM_ SG_ 2332819295 S2A_Num_CellVoltSensors_Rack31 "支路上的电芯电压传感器数量 ";
CM_ SG_ 2332819296 S2A_LookUpTblCurr_32 "充电查表电流";
CM_ SG_ 2332819296 S2A_NominalCellVol32 "·";
CM_ SG_ 2332819296 S2A_Limit_CellChargeVol_32 "电芯单体充电限制电压";
CM_ SG_ 2332819296 S2A_Limit_CellDisChargeVol_32 "电芯单体放电限制电压";
CM_ SG_ 2332819296 S2A_Num_CellVoltSensors_Rack32 "支路上的电芯电压传感器数量 ";
CM_ SG_ 2332819297 S2A_LookUpTblCurr_33 "充电查表电流";
CM_ SG_ 2332819297 S2A_NominalCellVol33 "·";
CM_ SG_ 2332819297 S2A_Limit_CellChargeVol_33 "电芯单体充电限制电压";
CM_ SG_ 2332819297 S2A_Limit_CellDisChargeVol_33 "电芯单体放电限制电压";
CM_ SG_ 2332819297 S2A_Num_CellVoltSensors_Rack33 "支路上的电芯电压传感器数量 ";
CM_ SG_ 2332819298 S2A_LookUpTblCurr_34 "充电查表电流";
CM_ SG_ 2332819298 S2A_NominalCellVol34 "·";
CM_ SG_ 2332819298 S2A_Limit_CellChargeVol_34 "电芯单体充电限制电压";
CM_ SG_ 2332819298 S2A_Limit_CellDisChargeVol_34 "电芯单体放电限制电压";
CM_ SG_ 2332819298 S2A_Num_CellVoltSensors_Rack34 "支路上的电芯电压传感器数量 ";
CM_ SG_ 2332819299 S2A_LookUpTblCurr_35 "充电查表电流";
CM_ SG_ 2332819299 S2A_NominalCellVol35 "·";
CM_ SG_ 2332819299 S2A_Limit_CellChargeVol_35 "电芯单体充电限制电压";
CM_ SG_ 2332819299 S2A_Limit_CellDisChargeVol_35 "电芯单体放电限制电压";
CM_ SG_ 2332819299 S2A_Num_CellVoltSensors_Rack35 "支路上的电芯电压传感器数量 ";
CM_ SG_ 2332819300 S2A_LookUpTblCurr_36 "充电查表电流";
CM_ SG_ 2332819300 S2A_NominalCellVol36 "·";
CM_ SG_ 2332819300 S2A_Limit_CellChargeVol_36 "电芯单体充电限制电压";
CM_ SG_ 2332819300 S2A_Limit_CellDisChargeVol_36 "电芯单体放电限制电压";
CM_ SG_ 2332819300 S2A_Num_CellVoltSensors_Rack36 "支路上的电芯电压传感器数量 ";
CM_ SG_ 2332819301 S2A_LookUpTblCurr_37 "充电查表电流";
CM_ SG_ 2332819301 S2A_NominalCellVol37 "·";
CM_ SG_ 2332819301 S2A_Limit_CellChargeVol_37 "电芯单体充电限制电压";
CM_ SG_ 2332819301 S2A_Limit_CellDisChargeVol_37 "电芯单体放电限制电压";
CM_ SG_ 2332819301 S2A_Num_CellVoltSensors_Rack37 "支路上的电芯电压传感器数量 ";
CM_ SG_ 2332819302 S2A_LookUpTblCurr_38 "充电查表电流";
CM_ SG_ 2332819302 S2A_NominalCellVol38 "·";
CM_ SG_ 2332819302 S2A_Limit_CellChargeVol_38 "电芯单体充电限制电压";
CM_ SG_ 2332819302 S2A_Limit_CellDisChargeVol_38 "电芯单体放电限制电压";
CM_ SG_ 2332819302 S2A_Num_CellVoltSensors_Rack38 "支路上的电芯电压传感器数量 ";
CM_ SG_ 2332819303 S2A_LookUpTblCurr_39 "充电查表电流";
CM_ SG_ 2332819303 S2A_NominalCellVol39 "·";
CM_ SG_ 2332819303 S2A_Limit_CellChargeVol_39 "电芯单体充电限制电压";
CM_ SG_ 2332819303 S2A_Limit_CellDisChargeVol_39 "电芯单体放电限制电压";
CM_ SG_ 2332819303 S2A_Num_CellVoltSensors_Rack39 "支路上的电芯电压传感器数量 ";
CM_ SG_ 2332819304 S2A_LookUpTblCurr_40 "充电查表电流";
CM_ SG_ 2332819304 S2A_NominalCellVol40 "·";
CM_ SG_ 2332819304 S2A_Limit_CellChargeVol_40 "电芯单体充电限制电压";
CM_ SG_ 2332819304 S2A_Limit_CellDisChargeVol_40 "电芯单体放电限制电压";
CM_ SG_ 2332819304 S2A_Num_CellVoltSensors_Rack40 "支路上的电芯电压传感器数量 ";
CM_ SG_ 2332819305 S2A_LookUpTblCurr_41 "充电查表电流";
CM_ SG_ 2332819305 S2A_NominalCellVol41 "·";
CM_ SG_ 2332819305 S2A_Limit_CellChargeVol_41 "电芯单体充电限制电压";
CM_ SG_ 2332819305 S2A_Limit_CellDisChargeVol_41 "电芯单体放电限制电压";
CM_ SG_ 2332819305 S2A_Num_CellVoltSensors_Rack41 "支路上的电芯电压传感器数量 ";
CM_ SG_ 2332819306 S2A_LookUpTblCurr_42 "充电查表电流";
CM_ SG_ 2332819306 S2A_NominalCellVol42 "·";
CM_ SG_ 2332819306 S2A_Limit_CellChargeVol_42 "电芯单体充电限制电压";
CM_ SG_ 2332819306 S2A_Limit_CellDisChargeVol_42 "电芯单体放电限制电压";
CM_ SG_ 2332819306 S2A_Num_CellVoltSensors_Rack42 "支路上的电芯电压传感器数量 ";
CM_ SG_ 2332819307 S2A_LookUpTblCurr_43 "充电查表电流";
CM_ SG_ 2332819307 S2A_NominalCellVol43 "·";
CM_ SG_ 2332819307 S2A_Limit_CellChargeVol_43 "电芯单体充电限制电压";
CM_ SG_ 2332819307 S2A_Limit_CellDisChargeVol_43 "电芯单体放电限制电压";
CM_ SG_ 2332819307 S2A_Num_CellVoltSensors_Rack43 "支路上的电芯电压传感器数量 ";
CM_ SG_ 2332819308 S2A_LookUpTblCurr_44 "充电查表电流";
CM_ SG_ 2332819308 S2A_NominalCellVol44 "·";
CM_ SG_ 2332819308 S2A_Limit_CellChargeVol_44 "电芯单体充电限制电压";
CM_ SG_ 2332819308 S2A_Limit_CellDisChargeVol_44 "电芯单体放电限制电压";
CM_ SG_ 2332819308 S2A_Num_CellVoltSensors_Rack44 "支路上的电芯电压传感器数量 ";
CM_ SG_ 2332819309 S2A_LookUpTblCurr_45 "充电查表电流";
CM_ SG_ 2332819309 S2A_NominalCellVol45 "·";
CM_ SG_ 2332819309 S2A_Limit_CellChargeVol_45 "电芯单体充电限制电压";
CM_ SG_ 2332819309 S2A_Limit_CellDisChargeVol_45 "电芯单体放电限制电压";
CM_ SG_ 2332819309 S2A_Num_CellVoltSensors_Rack45 "支路上的电芯电压传感器数量 ";
CM_ SG_ 2332819310 S2A_LookUpTblCurr_46 "充电查表电流";
CM_ SG_ 2332819310 S2A_NominalCellVol46 "·";
CM_ SG_ 2332819310 S2A_Limit_CellChargeVol_46 "电芯单体充电限制电压";
CM_ SG_ 2332819310 S2A_Limit_CellDisChargeVol_46 "电芯单体放电限制电压";
CM_ SG_ 2332819310 S2A_Num_CellVoltSensors_Rack46 "支路上的电芯电压传感器数量 ";
CM_ SG_ 2332819311 S2A_LookUpTblCurr_47 "充电查表电流";
CM_ SG_ 2332819311 S2A_NominalCellVol47 "·";
CM_ SG_ 2332819311 S2A_Limit_CellChargeVol_47 "电芯单体充电限制电压";
CM_ SG_ 2332819311 S2A_Limit_CellDisChargeVol_47 "电芯单体放电限制电压";
CM_ SG_ 2332819311 S2A_Num_CellVoltSensors_Rack47 "支路上的电芯电压传感器数量 ";
CM_ SG_ 2332819312 S2A_LookUpTblCurr_48 "充电查表电流";
CM_ SG_ 2332819312 S2A_NominalCellVol48 "·";
CM_ SG_ 2332819312 S2A_Limit_CellChargeVol_48 "电芯单体充电限制电压";
CM_ SG_ 2332819312 S2A_Limit_CellDisChargeVol_48 "电芯单体放电限制电压";
CM_ SG_ 2332819312 S2A_Num_CellVoltSensors_Rack48 "支路上的电芯电压传感器数量 ";
CM_ SG_ 2332819313 S2A_LookUpTblCurr_49 "充电查表电流";
CM_ SG_ 2332819313 S2A_NominalCellVol49 "·";
CM_ SG_ 2332819313 S2A_Limit_CellChargeVol_49 "电芯单体充电限制电压";
CM_ SG_ 2332819313 S2A_Limit_CellDisChargeVol_49 "电芯单体放电限制电压";
CM_ SG_ 2332819313 S2A_Num_CellVoltSensors_Rack49 "支路上的电芯电压传感器数量 ";
CM_ SG_ 2332819314 S2A_LookUpTblCurr_50 "充电查表电流";
CM_ SG_ 2332819314 S2A_NominalCellVol50 "·";
CM_ SG_ 2332819314 S2A_Limit_CellChargeVol_50 "电芯单体充电限制电压";
CM_ SG_ 2332819314 S2A_Limit_CellDisChargeVol_50 "电芯单体放电限制电压";
CM_ SG_ 2332819314 S2A_Num_CellVoltSensors_Rack50 "支路上的电芯电压传感器数量 ";
CM_ SG_ 2332819315 S2A_LookUpTblCurr_51 "充电查表电流";
CM_ SG_ 2332819315 S2A_NominalCellVol51 "·";
CM_ SG_ 2332819315 S2A_Limit_CellChargeVol_51 "电芯单体充电限制电压";
CM_ SG_ 2332819315 S2A_Limit_CellDisChargeVol_51 "电芯单体放电限制电压";
CM_ SG_ 2332819315 S2A_Num_CellVoltSensors_Rack51 "支路上的电芯电压传感器数量 ";
CM_ SG_ 2332819316 S2A_LookUpTblCurr_52 "充电查表电流";
CM_ SG_ 2332819316 S2A_NominalCellVol52 "·";
CM_ SG_ 2332819316 S2A_Limit_CellChargeVol_52 "电芯单体充电限制电压";
CM_ SG_ 2332819316 S2A_Limit_CellDisChargeVol_52 "电芯单体放电限制电压";
CM_ SG_ 2332819316 S2A_Num_CellVoltSensors_Rack52 "支路上的电芯电压传感器数量 ";
CM_ SG_ 2332819317 S2A_LookUpTblCurr_53 "充电查表电流";
CM_ SG_ 2332819317 S2A_NominalCellVol53 "·";
CM_ SG_ 2332819317 S2A_Limit_CellChargeVol_53 "电芯单体充电限制电压";
CM_ SG_ 2332819317 S2A_Limit_CellDisChargeVol_53 "电芯单体放电限制电压";
CM_ SG_ 2332819317 S2A_Num_CellVoltSensors_Rack53 "支路上的电芯电压传感器数量 ";
CM_ SG_ 2332819318 S2A_LookUpTblCurr_54 "充电查表电流";
CM_ SG_ 2332819318 S2A_NominalCellVol54 "·";
CM_ SG_ 2332819318 S2A_Limit_CellChargeVol_54 "电芯单体充电限制电压";
CM_ SG_ 2332819318 S2A_Limit_CellDisChargeVol_54 "电芯单体放电限制电压";
CM_ SG_ 2332819318 S2A_Num_CellVoltSensors_Rack54 "支路上的电芯电压传感器数量 ";
CM_ SG_ 2332819319 S2A_LookUpTblCurr_55 "充电查表电流";
CM_ SG_ 2332819319 S2A_NominalCellVol55 "·";
CM_ SG_ 2332819319 S2A_Limit_CellChargeVol_55 "电芯单体充电限制电压";
CM_ SG_ 2332819319 S2A_Limit_CellDisChargeVol_55 "电芯单体放电限制电压";
CM_ SG_ 2332819319 S2A_Num_CellVoltSensors_Rack55 "支路上的电芯电压传感器数量 ";
CM_ SG_ 2332819320 S2A_LookUpTblCurr_56 "充电查表电流";
CM_ SG_ 2332819320 S2A_NominalCellVol56 "·";
CM_ SG_ 2332819320 S2A_Limit_CellChargeVol_56 "电芯单体充电限制电压";
CM_ SG_ 2332819320 S2A_Limit_CellDisChargeVol_56 "电芯单体放电限制电压";
CM_ SG_ 2332819320 S2A_Num_CellVoltSensors_Rack56 "支路上的电芯电压传感器数量 ";
CM_ SG_ 2332819321 S2A_LookUpTblCurr_57 "充电查表电流";
CM_ SG_ 2332819321 S2A_NominalCellVol57 "·";
CM_ SG_ 2332819321 S2A_Limit_CellChargeVol_57 "电芯单体充电限制电压";
CM_ SG_ 2332819321 S2A_Limit_CellDisChargeVol_57 "电芯单体放电限制电压";
CM_ SG_ 2332819321 S2A_Num_CellVoltSensors_Rack57 "支路上的电芯电压传感器数量 ";
CM_ SG_ 2332819322 S2A_LookUpTblCurr_58 "充电查表电流";
CM_ SG_ 2332819322 S2A_NominalCellVol58 "·";
CM_ SG_ 2332819322 S2A_Limit_CellChargeVol_58 "电芯单体充电限制电压";
CM_ SG_ 2332819322 S2A_Limit_CellDisChargeVol_58 "电芯单体放电限制电压";
CM_ SG_ 2332819322 S2A_Num_CellVoltSensors_Rack58 "支路上的电芯电压传感器数量 ";
CM_ SG_ 2332819323 S2A_LookUpTblCurr_59 "充电查表电流";
CM_ SG_ 2332819323 S2A_NominalCellVol59 "·";
CM_ SG_ 2332819323 S2A_Limit_CellChargeVol_59 "电芯单体充电限制电压";
CM_ SG_ 2332819323 S2A_Limit_CellDisChargeVol_59 "电芯单体放电限制电压";
CM_ SG_ 2332819323 S2A_Num_CellVoltSensors_Rack59 "支路上的电芯电压传感器数量 ";
CM_ SG_ 2332819324 S2A_LookUpTblCurr_60 "充电查表电流";
CM_ SG_ 2332819324 S2A_NominalCellVol60 "·";
CM_ SG_ 2332819324 S2A_Limit_CellChargeVol_60 "电芯单体充电限制电压";
CM_ SG_ 2332819324 S2A_Limit_CellDisChargeVol_60 "电芯单体放电限制电压";
CM_ SG_ 2332819324 S2A_Num_CellVoltSensors_Rack60 "支路上的电芯电压传感器数量 ";
CM_ SG_ 2332819325 S2A_LookUpTblCurr_61 "充电查表电流";
CM_ SG_ 2332819325 S2A_NominalCellVol61 "·";
CM_ SG_ 2332819325 S2A_Limit_CellChargeVol_61 "电芯单体充电限制电压";
CM_ SG_ 2332819325 S2A_Limit_CellDisChargeVol_61 "电芯单体放电限制电压";
CM_ SG_ 2332819325 S2A_Num_CellVoltSensors_Rack61 "支路上的电芯电压传感器数量 ";
CM_ SG_ 2332819326 S2A_LookUpTblCurr_62 "充电查表电流";
CM_ SG_ 2332819326 S2A_NominalCellVol62 "·";
CM_ SG_ 2332819326 S2A_Limit_CellChargeVol_62 "电芯单体充电限制电压";
CM_ SG_ 2332819326 S2A_Limit_CellDisChargeVol_62 "电芯单体放电限制电压";
CM_ SG_ 2332819326 S2A_Num_CellVoltSensors_Rack62 "支路上的电芯电压传感器数量 ";
CM_ SG_ 2332819327 S2A_LookUpTblCurr_63 "充电查表电流";
CM_ SG_ 2332819327 S2A_NominalCellVol63 "·";
CM_ SG_ 2332819327 S2A_Limit_CellChargeVol_63 "电芯单体充电限制电压";
CM_ SG_ 2332819327 S2A_Limit_CellDisChargeVol_63 "电芯单体放电限制电压";
CM_ SG_ 2332819327 S2A_Num_CellVoltSensors_Rack63 "支路上的电芯电压传感器数量 ";
CM_ SG_ 2333212481 S2A_BAT_I_HVS_01 "电柜采集电流";
CM_ SG_ 2333212481 BAT_U_INNER_HVS_01 "电柜内侧高压采样";
CM_ SG_ 2333212481 BAT_Pwr_01 "单柜实时功率";
CM_ SG_ 2333212481 S2A_SBMU_FaultClass_01 "SBMU故障等级";
CM_ SG_ 2333212481 ExtinguishingValve_Drive "灭火剂阀门驱动信号";
CM_ SG_ 2333212482 S2A_BAT_I_HVS_02 "电柜采集电流";
CM_ SG_ 2333212482 BAT_U_INNER_HVS_02 "电柜内侧高压采样";
CM_ SG_ 2333212482 BAT_Pwr_02 "单柜实时功率";
CM_ SG_ 2333212482 S2A_SBMU_FaultClass_02 "SBMU故障等级";
CM_ SG_ 2333212482 ExtinguishingValve_Drive "灭火剂阀门驱动信号";
CM_ SG_ 2333212483 S2A_BAT_I_HVS_03 "电柜采集电流";
CM_ SG_ 2333212483 BAT_U_INNER_HVS_03 "电柜内侧高压采样";
CM_ SG_ 2333212483 BAT_Pwr_03 "单柜实时功率";
CM_ SG_ 2333212483 S2A_SBMU_FaultClass_03 "SBMU故障等级";
CM_ SG_ 2333212483 ExtinguishingValve_Drive "灭火剂阀门驱动信号";
CM_ SG_ 2333212484 S2A_BAT_I_HVS_04 "电柜采集电流";
CM_ SG_ 2333212484 BAT_U_INNER_HVS_04 "电柜内侧高压采样";
CM_ SG_ 2333212484 BAT_Pwr_04 "单柜实时功率";
CM_ SG_ 2333212484 S2A_SBMU_FaultClass_04 "SBMU故障等级";
CM_ SG_ 2333212484 ExtinguishingValve_Drive "灭火剂阀门驱动信号";
CM_ SG_ 2333212485 S2A_BAT_I_HVS_05 "电柜采集电流";
CM_ SG_ 2333212485 BAT_U_INNER_HVS_05 "电柜内侧高压采样";
CM_ SG_ 2333212485 BAT_Pwr_05 "单柜实时功率";
CM_ SG_ 2333212485 S2A_SBMU_FaultClass_05 "SBMU故障等级";
CM_ SG_ 2333212485 ExtinguishingValve_Drive "灭火剂阀门驱动信号";
CM_ SG_ 2333212486 S2A_BAT_I_HVS_06 "电柜采集电流";
CM_ SG_ 2333212486 BAT_U_INNER_HVS_06 "电柜内侧高压采样";
CM_ SG_ 2333212486 BAT_Pwr_06 "单柜实时功率";
CM_ SG_ 2333212486 S2A_SBMU_FaultClass_06 "SBMU故障等级";
CM_ SG_ 2333212486 ExtinguishingValve_Drive "灭火剂阀门驱动信号";
CM_ SG_ 2333212487 S2A_BAT_I_HVS_07 "电柜采集电流";
CM_ SG_ 2333212487 BAT_U_INNER_HVS_07 "电柜内侧高压采样";
CM_ SG_ 2333212487 BAT_Pwr_07 "单柜实时功率";
CM_ SG_ 2333212487 S2A_SBMU_FaultClass_07 "SBMU故障等级";
CM_ SG_ 2333212487 ExtinguishingValve_Drive "灭火剂阀门驱动信号";
CM_ SG_ 2333212488 S2A_BAT_I_HVS_08 "电柜采集电流";
CM_ SG_ 2333212488 BAT_U_INNER_HVS_08 "电柜内侧高压采样";
CM_ SG_ 2333212488 BAT_Pwr_08 "单柜实时功率";
CM_ SG_ 2333212488 S2A_SBMU_FaultClass_08 "SBMU故障等级";
CM_ SG_ 2333212488 ExtinguishingValve_Drive "灭火剂阀门驱动信号";
CM_ SG_ 2333212489 S2A_BAT_I_HVS_09 "电柜采集电流";
CM_ SG_ 2333212489 BAT_U_INNER_HVS_09 "电柜内侧高压采样";
CM_ SG_ 2333212489 BAT_Pwr_09 "单柜实时功率";
CM_ SG_ 2333212489 S2A_SBMU_FaultClass_09 "SBMU故障等级";
CM_ SG_ 2333212489 ExtinguishingValve_Drive "灭火剂阀门驱动信号";
CM_ SG_ 2333212490 S2A_BAT_I_HVS_10 "电柜采集电流";
CM_ SG_ 2333212490 BAT_U_INNER_HVS_10 "电柜内侧高压采样";
CM_ SG_ 2333212490 BAT_Pwr_10 "单柜实时功率";
CM_ SG_ 2333212490 S2A_SBMU_FaultClass_10 "SBMU故障等级";
CM_ SG_ 2333212490 ExtinguishingValve_Drive "灭火剂阀门驱动信号";
CM_ SG_ 2333212491 S2A_BAT_I_HVS_11 "电柜采集电流";
CM_ SG_ 2333212491 BAT_U_INNER_HVS_11 "电柜内侧高压采样";
CM_ SG_ 2333212491 BAT_Pwr_11 "单柜实时功率";
CM_ SG_ 2333212491 S2A_SBMU_FaultClass_11 "SBMU故障等级";
CM_ SG_ 2333212491 ExtinguishingValve_Drive "灭火剂阀门驱动信号";
CM_ SG_ 2333212492 S2A_BAT_I_HVS_12 "电柜采集电流";
CM_ SG_ 2333212492 BAT_U_INNER_HVS_12 "电柜内侧高压采样";
CM_ SG_ 2333212492 BAT_Pwr_12 "单柜实时功率";
CM_ SG_ 2333212492 S2A_SBMU_FaultClass_12 "SBMU故障等级";
CM_ SG_ 2333212492 ExtinguishingValve_Drive "灭火剂阀门驱动信号";
CM_ SG_ 2333212493 S2A_BAT_I_HVS_13 "电柜采集电流";
CM_ SG_ 2333212493 BAT_U_INNER_HVS_13 "电柜内侧高压采样";
CM_ SG_ 2333212493 BAT_Pwr_13 "单柜实时功率";
CM_ SG_ 2333212493 S2A_SBMU_FaultClass_13 "SBMU故障等级";
CM_ SG_ 2333212493 ExtinguishingValve_Drive "灭火剂阀门驱动信号";
CM_ SG_ 2333212494 S2A_BAT_I_HVS_14 "电柜采集电流";
CM_ SG_ 2333212494 BAT_U_INNER_HVS_14 "电柜内侧高压采样";
CM_ SG_ 2333212494 BAT_Pwr_14 "单柜实时功率";
CM_ SG_ 2333212494 S2A_SBMU_FaultClass_14 "SBMU故障等级";
CM_ SG_ 2333212494 ExtinguishingValve_Drive "灭火剂阀门驱动信号";
CM_ SG_ 2333212495 S2A_BAT_I_HVS_15 "电柜采集电流";
CM_ SG_ 2333212495 BAT_U_INNER_HVS_15 "电柜内侧高压采样";
CM_ SG_ 2333212495 BAT_Pwr_15 "单柜实时功率";
CM_ SG_ 2333212495 S2A_SBMU_FaultClass_15 "SBMU故障等级";
CM_ SG_ 2333212495 ExtinguishingValve_Drive "灭火剂阀门驱动信号";
CM_ SG_ 2333212496 S2A_BAT_I_HVS_16 "电柜采集电流";
CM_ SG_ 2333212496 BAT_U_INNER_HVS_16 "电柜内侧高压采样";
CM_ SG_ 2333212496 BAT_Pwr_16 "单柜实时功率";
CM_ SG_ 2333212496 S2A_SBMU_FaultClass_16 "SBMU故障等级";
CM_ SG_ 2333212496 ExtinguishingValve_Drive "灭火剂阀门驱动信号";
CM_ SG_ 2333212497 S2A_BAT_I_HVS_17 "电柜采集电流";
CM_ SG_ 2333212497 BAT_U_INNER_HVS_17 "电柜内侧高压采样";
CM_ SG_ 2333212497 BAT_Pwr_17 "单柜实时功率";
CM_ SG_ 2333212497 S2A_SBMU_FaultClass_17 "SBMU故障等级";
CM_ SG_ 2333212497 ExtinguishingValve_Drive "灭火剂阀门驱动信号";
CM_ SG_ 2333212498 S2A_BAT_I_HVS_18 "电柜采集电流";
CM_ SG_ 2333212498 BAT_U_INNER_HVS_18 "电柜内侧高压采样";
CM_ SG_ 2333212498 BAT_Pwr_18 "单柜实时功率";
CM_ SG_ 2333212498 S2A_SBMU_FaultClass_18 "SBMU故障等级";
CM_ SG_ 2333212498 ExtinguishingValve_Drive "灭火剂阀门驱动信号";
CM_ SG_ 2333212499 S2A_BAT_I_HVS_19 "电柜采集电流";
CM_ SG_ 2333212499 BAT_U_INNER_HVS_19 "电柜内侧高压采样";
CM_ SG_ 2333212499 BAT_Pwr_19 "单柜实时功率";
CM_ SG_ 2333212499 S2A_SBMU_FaultClass_19 "SBMU故障等级";
CM_ SG_ 2333212499 ExtinguishingValve_Drive "灭火剂阀门驱动信号";
CM_ SG_ 2333212500 S2A_BAT_I_HVS_20 "电柜采集电流";
CM_ SG_ 2333212500 BAT_U_INNER_HVS_20 "电柜内侧高压采样";
CM_ SG_ 2333212500 BAT_Pwr_20 "单柜实时功率";
CM_ SG_ 2333212500 S2A_SBMU_FaultClass_20 "SBMU故障等级";
CM_ SG_ 2333212500 ExtinguishingValve_Drive "灭火剂阀门驱动信号";
CM_ SG_ 2333212501 S2A_BAT_I_HVS_21 "电柜采集电流";
CM_ SG_ 2333212501 BAT_U_INNER_HVS_21 "电柜内侧高压采样";
CM_ SG_ 2333212501 BAT_Pwr_21 "单柜实时功率";
CM_ SG_ 2333212501 S2A_SBMU_FaultClass_21 "SBMU故障等级";
CM_ SG_ 2333212501 ExtinguishingValve_Drive "灭火剂阀门驱动信号";
CM_ SG_ 2333212502 S2A_BAT_I_HVS_22 "电柜采集电流";
CM_ SG_ 2333212502 BAT_U_INNER_HVS_22 "电柜内侧高压采样";
CM_ SG_ 2333212502 BAT_Pwr_22 "单柜实时功率";
CM_ SG_ 2333212502 S2A_SBMU_FaultClass_22 "SBMU故障等级";
CM_ SG_ 2333212502 ExtinguishingValve_Drive "灭火剂阀门驱动信号";
CM_ SG_ 2333212503 S2A_BAT_I_HVS_23 "电柜采集电流";
CM_ SG_ 2333212503 BAT_U_INNER_HVS_23 "电柜内侧高压采样";
CM_ SG_ 2333212503 BAT_Pwr_23 "单柜实时功率";
CM_ SG_ 2333212503 S2A_SBMU_FaultClass_23 "SBMU故障等级";
CM_ SG_ 2333212503 ExtinguishingValve_Drive "灭火剂阀门驱动信号";
CM_ SG_ 2333212504 S2A_BAT_I_HVS_24 "电柜采集电流";
CM_ SG_ 2333212504 BAT_U_INNER_HVS_24 "电柜内侧高压采样";
CM_ SG_ 2333212504 BAT_Pwr_24 "单柜实时功率";
CM_ SG_ 2333212504 S2A_SBMU_FaultClass_24 "SBMU故障等级";
CM_ SG_ 2333212504 ExtinguishingValve_Drive "灭火剂阀门驱动信号";
CM_ SG_ 2333212505 S2A_BAT_I_HVS_25 "电柜采集电流";
CM_ SG_ 2333212505 BAT_U_INNER_HVS_25 "电柜内侧高压采样";
CM_ SG_ 2333212505 BAT_Pwr_25 "单柜实时功率";
CM_ SG_ 2333212505 S2A_SBMU_FaultClass_25 "SBMU故障等级";
CM_ SG_ 2333212505 ExtinguishingValve_Drive "灭火剂阀门驱动信号";
CM_ SG_ 2333212506 S2A_BAT_I_HVS_26 "电柜采集电流";
CM_ SG_ 2333212506 BAT_U_INNER_HVS_26 "电柜内侧高压采样";
CM_ SG_ 2333212506 BAT_Pwr_26 "单柜实时功率";
CM_ SG_ 2333212506 S2A_SBMU_FaultClass_26 "SBMU故障等级";
CM_ SG_ 2333212506 ExtinguishingValve_Drive "灭火剂阀门驱动信号";
CM_ SG_ 2333212507 S2A_BAT_I_HVS_27 "电柜采集电流";
CM_ SG_ 2333212507 BAT_U_INNER_HVS_27 "电柜内侧高压采样";
CM_ SG_ 2333212507 BAT_Pwr_27 "单柜实时功率";
CM_ SG_ 2333212507 S2A_SBMU_FaultClass_27 "SBMU故障等级";
CM_ SG_ 2333212507 ExtinguishingValve_Drive "灭火剂阀门驱动信号";
CM_ SG_ 2333212508 S2A_BAT_I_HVS_28 "电柜采集电流";
CM_ SG_ 2333212508 BAT_U_INNER_HVS_28 "电柜内侧高压采样";
CM_ SG_ 2333212508 BAT_Pwr_28 "单柜实时功率";
CM_ SG_ 2333212508 S2A_SBMU_FaultClass_28 "SBMU故障等级";
CM_ SG_ 2333212508 ExtinguishingValve_Drive "灭火剂阀门驱动信号";
CM_ SG_ 2333212509 S2A_BAT_I_HVS_29 "电柜采集电流";
CM_ SG_ 2333212509 BAT_U_INNER_HVS_29 "电柜内侧高压采样";
CM_ SG_ 2333212509 BAT_Pwr_29 "单柜实时功率";
CM_ SG_ 2333212509 S2A_SBMU_FaultClass_29 "SBMU故障等级";
CM_ SG_ 2333212509 ExtinguishingValve_Drive "灭火剂阀门驱动信号";
CM_ SG_ 2333212510 S2A_BAT_I_HVS_30 "电柜采集电流";
CM_ SG_ 2333212510 BAT_U_INNER_HVS_30 "电柜内侧高压采样";
CM_ SG_ 2333212510 BAT_Pwr_30 "单柜实时功率";
CM_ SG_ 2333212510 S2A_SBMU_FaultClass_30 "SBMU故障等级";
CM_ SG_ 2333212510 ExtinguishingValve_Drive "灭火剂阀门驱动信号";
CM_ SG_ 2333212511 S2A_BAT_I_HVS_31 "电柜采集电流";
CM_ SG_ 2333212511 BAT_U_INNER_HVS_31 "电柜内侧高压采样";
CM_ SG_ 2333212511 BAT_Pwr_31 "单柜实时功率";
CM_ SG_ 2333212511 S2A_SBMU_FaultClass_31 "SBMU故障等级";
CM_ SG_ 2333212511 ExtinguishingValve_Drive "灭火剂阀门驱动信号";
CM_ SG_ 2333212512 S2A_BAT_I_HVS_32 "电柜采集电流";
CM_ SG_ 2333212512 BAT_U_INNER_HVS_32 "电柜内侧高压采样";
CM_ SG_ 2333212512 BAT_Pwr_32 "单柜实时功率";
CM_ SG_ 2333212512 S2A_SBMU_FaultClass_32 "SBMU故障等级";
CM_ SG_ 2333212512 ExtinguishingValve_Drive "灭火剂阀门驱动信号";
CM_ SG_ 2333212513 S2A_BAT_I_HVS_33 "电柜采集电流";
CM_ SG_ 2333212513 BAT_U_INNER_HVS_33 "电柜内侧高压采样";
CM_ SG_ 2333212513 BAT_Pwr_33 "单柜实时功率";
CM_ SG_ 2333212513 S2A_SBMU_FaultClass_33 "SBMU故障等级";
CM_ SG_ 2333212513 ExtinguishingValve_Drive "灭火剂阀门驱动信号";
CM_ SG_ 2333212514 S2A_BAT_I_HVS_34 "电柜采集电流";
CM_ SG_ 2333212514 BAT_U_INNER_HVS_34 "电柜内侧高压采样";
CM_ SG_ 2333212514 BAT_Pwr_34 "单柜实时功率";
CM_ SG_ 2333212514 S2A_SBMU_FaultClass_34 "SBMU故障等级";
CM_ SG_ 2333212514 ExtinguishingValve_Drive "灭火剂阀门驱动信号";
CM_ SG_ 2333212515 S2A_BAT_I_HVS_35 "电柜采集电流";
CM_ SG_ 2333212515 BAT_U_INNER_HVS_35 "电柜内侧高压采样";
CM_ SG_ 2333212515 BAT_Pwr_35 "单柜实时功率";
CM_ SG_ 2333212515 S2A_SBMU_FaultClass_35 "SBMU故障等级";
CM_ SG_ 2333212515 ExtinguishingValve_Drive "灭火剂阀门驱动信号";
CM_ SG_ 2333212516 S2A_BAT_I_HVS_36 "电柜采集电流";
CM_ SG_ 2333212516 BAT_U_INNER_HVS_36 "电柜内侧高压采样";
CM_ SG_ 2333212516 BAT_Pwr_36 "单柜实时功率";
CM_ SG_ 2333212516 S2A_SBMU_FaultClass_36 "SBMU故障等级";
CM_ SG_ 2333212516 ExtinguishingValve_Drive "灭火剂阀门驱动信号";
CM_ SG_ 2333212517 S2A_BAT_I_HVS_37 "电柜采集电流";
CM_ SG_ 2333212517 BAT_U_INNER_HVS_37 "电柜内侧高压采样";
CM_ SG_ 2333212517 BAT_Pwr_37 "单柜实时功率";
CM_ SG_ 2333212517 S2A_SBMU_FaultClass_37 "SBMU故障等级";
CM_ SG_ 2333212517 ExtinguishingValve_Drive "灭火剂阀门驱动信号";
CM_ SG_ 2333212518 S2A_BAT_I_HVS_38 "电柜采集电流";
CM_ SG_ 2333212518 BAT_U_INNER_HVS_38 "电柜内侧高压采样";
CM_ SG_ 2333212518 BAT_Pwr_38 "单柜实时功率";
CM_ SG_ 2333212518 S2A_SBMU_FaultClass_38 "SBMU故障等级";
CM_ SG_ 2333212518 ExtinguishingValve_Drive "灭火剂阀门驱动信号";
CM_ SG_ 2333212519 S2A_BAT_I_HVS_39 "电柜采集电流";
CM_ SG_ 2333212519 BAT_U_INNER_HVS_39 "电柜内侧高压采样";
CM_ SG_ 2333212519 BAT_Pwr_39 "单柜实时功率";
CM_ SG_ 2333212519 S2A_SBMU_FaultClass_39 "SBMU故障等级";
CM_ SG_ 2333212519 ExtinguishingValve_Drive "灭火剂阀门驱动信号";
CM_ SG_ 2333212520 S2A_BAT_I_HVS_40 "电柜采集电流";
CM_ SG_ 2333212520 BAT_U_INNER_HVS_40 "电柜内侧高压采样";
CM_ SG_ 2333212520 BAT_Pwr_40 "单柜实时功率";
CM_ SG_ 2333212520 S2A_SBMU_FaultClass_40 "SBMU故障等级";
CM_ SG_ 2333212520 ExtinguishingValve_Drive "灭火剂阀门驱动信号";
CM_ SG_ 2333212521 S2A_BAT_I_HVS_41 "电柜采集电流";
CM_ SG_ 2333212521 BAT_U_INNER_HVS_41 "电柜内侧高压采样";
CM_ SG_ 2333212521 BAT_Pwr_41 "单柜实时功率";
CM_ SG_ 2333212521 S2A_SBMU_FaultClass_41 "SBMU故障等级";
CM_ SG_ 2333212521 ExtinguishingValve_Drive "灭火剂阀门驱动信号";
CM_ SG_ 2333212522 S2A_BAT_I_HVS_42 "电柜采集电流";
CM_ SG_ 2333212522 BAT_U_INNER_HVS_42 "电柜内侧高压采样";
CM_ SG_ 2333212522 BAT_Pwr_42 "单柜实时功率";
CM_ SG_ 2333212522 S2A_SBMU_FaultClass_42 "SBMU故障等级";
CM_ SG_ 2333212522 ExtinguishingValve_Drive "灭火剂阀门驱动信号";
CM_ SG_ 2333212523 S2A_BAT_I_HVS_43 "电柜采集电流";
CM_ SG_ 2333212523 BAT_U_INNER_HVS_43 "电柜内侧高压采样";
CM_ SG_ 2333212523 BAT_Pwr_43 "单柜实时功率";
CM_ SG_ 2333212523 S2A_SBMU_FaultClass_43 "SBMU故障等级";
CM_ SG_ 2333212523 ExtinguishingValve_Drive "灭火剂阀门驱动信号";
CM_ SG_ 2333212524 S2A_BAT_I_HVS_44 "电柜采集电流";
CM_ SG_ 2333212524 BAT_U_INNER_HVS_44 "电柜内侧高压采样";
CM_ SG_ 2333212524 BAT_Pwr_44 "单柜实时功率";
CM_ SG_ 2333212524 S2A_SBMU_FaultClass_44 "SBMU故障等级";
CM_ SG_ 2333212524 ExtinguishingValve_Drive "灭火剂阀门驱动信号";
CM_ SG_ 2333212525 S2A_BAT_I_HVS_45 "电柜采集电流";
CM_ SG_ 2333212525 BAT_U_INNER_HVS_45 "电柜内侧高压采样";
CM_ SG_ 2333212525 BAT_Pwr_45 "单柜实时功率";
CM_ SG_ 2333212525 S2A_SBMU_FaultClass_45 "SBMU故障等级";
CM_ SG_ 2333212525 ExtinguishingValve_Drive "灭火剂阀门驱动信号";
CM_ SG_ 2333212526 S2A_BAT_I_HVS_46 "电柜采集电流";
CM_ SG_ 2333212526 BAT_U_INNER_HVS_46 "电柜内侧高压采样";
CM_ SG_ 2333212526 BAT_Pwr_46 "单柜实时功率";
CM_ SG_ 2333212526 S2A_SBMU_FaultClass_46 "SBMU故障等级";
CM_ SG_ 2333212526 ExtinguishingValve_Drive "灭火剂阀门驱动信号";
CM_ SG_ 2333212527 S2A_BAT_I_HVS_47 "电柜采集电流";
CM_ SG_ 2333212527 BAT_U_INNER_HVS_47 "电柜内侧高压采样";
CM_ SG_ 2333212527 BAT_Pwr_47 "单柜实时功率";
CM_ SG_ 2333212527 S2A_SBMU_FaultClass_47 "SBMU故障等级";
CM_ SG_ 2333212527 ExtinguishingValve_Drive "灭火剂阀门驱动信号";
CM_ SG_ 2333212528 S2A_BAT_I_HVS_48 "电柜采集电流";
CM_ SG_ 2333212528 BAT_U_INNER_HVS_48 "电柜内侧高压采样";
CM_ SG_ 2333212528 BAT_Pwr_48 "单柜实时功率";
CM_ SG_ 2333212528 S2A_SBMU_FaultClass_48 "SBMU故障等级";
CM_ SG_ 2333212528 ExtinguishingValve_Drive "灭火剂阀门驱动信号";
CM_ SG_ 2333212529 S2A_BAT_I_HVS_49 "电柜采集电流";
CM_ SG_ 2333212529 BAT_U_INNER_HVS_49 "电柜内侧高压采样";
CM_ SG_ 2333212529 BAT_Pwr_49 "单柜实时功率";
CM_ SG_ 2333212529 S2A_SBMU_FaultClass_49 "SBMU故障等级";
CM_ SG_ 2333212529 ExtinguishingValve_Drive "灭火剂阀门驱动信号";
CM_ SG_ 2333212530 S2A_BAT_I_HVS_50 "电柜采集电流";
CM_ SG_ 2333212530 BAT_U_INNER_HVS_50 "电柜内侧高压采样";
CM_ SG_ 2333212530 BAT_Pwr_50 "单柜实时功率";
CM_ SG_ 2333212530 S2A_SBMU_FaultClass_50 "SBMU故障等级";
CM_ SG_ 2333212530 ExtinguishingValve_Drive "灭火剂阀门驱动信号";
CM_ SG_ 2333212531 S2A_BAT_I_HVS_51 "电柜采集电流";
CM_ SG_ 2333212531 BAT_U_INNER_HVS_51 "电柜内侧高压采样";
CM_ SG_ 2333212531 BAT_Pwr_51 "单柜实时功率";
CM_ SG_ 2333212531 S2A_SBMU_FaultClass_51 "SBMU故障等级";
CM_ SG_ 2333212531 ExtinguishingValve_Drive "灭火剂阀门驱动信号";
CM_ SG_ 2333212532 S2A_BAT_I_HVS_52 "电柜采集电流";
CM_ SG_ 2333212532 BAT_U_INNER_HVS_52 "电柜内侧高压采样";
CM_ SG_ 2333212532 BAT_Pwr_52 "单柜实时功率";
CM_ SG_ 2333212532 S2A_SBMU_FaultClass_52 "SBMU故障等级";
CM_ SG_ 2333212532 ExtinguishingValve_Drive "灭火剂阀门驱动信号";
CM_ SG_ 2333212533 S2A_BAT_I_HVS_53 "电柜采集电流";
CM_ SG_ 2333212533 BAT_U_INNER_HVS_53 "电柜内侧高压采样";
CM_ SG_ 2333212533 BAT_Pwr_53 "单柜实时功率";
CM_ SG_ 2333212533 S2A_SBMU_FaultClass_53 "SBMU故障等级";
CM_ SG_ 2333212533 ExtinguishingValve_Drive "灭火剂阀门驱动信号";
CM_ SG_ 2333212534 S2A_BAT_I_HVS_54 "电柜采集电流";
CM_ SG_ 2333212534 BAT_U_INNER_HVS_54 "电柜内侧高压采样";
CM_ SG_ 2333212534 BAT_Pwr_54 "单柜实时功率";
CM_ SG_ 2333212534 S2A_SBMU_FaultClass_54 "SBMU故障等级";
CM_ SG_ 2333212534 ExtinguishingValve_Drive "灭火剂阀门驱动信号";
CM_ SG_ 2333212535 S2A_BAT_I_HVS_55 "电柜采集电流";
CM_ SG_ 2333212535 BAT_U_INNER_HVS_55 "电柜内侧高压采样";
CM_ SG_ 2333212535 BAT_Pwr_55 "单柜实时功率";
CM_ SG_ 2333212535 S2A_SBMU_FaultClass_55 "SBMU故障等级";
CM_ SG_ 2333212535 ExtinguishingValve_Drive "灭火剂阀门驱动信号";
CM_ SG_ 2333212536 S2A_BAT_I_HVS_56 "电柜采集电流";
CM_ SG_ 2333212536 BAT_U_INNER_HVS_56 "电柜内侧高压采样";
CM_ SG_ 2333212536 BAT_Pwr_56 "单柜实时功率";
CM_ SG_ 2333212536 S2A_SBMU_FaultClass_56 "SBMU故障等级";
CM_ SG_ 2333212536 ExtinguishingValve_Drive "灭火剂阀门驱动信号";
CM_ SG_ 2333212537 S2A_BAT_I_HVS_57 "电柜采集电流";
CM_ SG_ 2333212537 BAT_U_INNER_HVS_57 "电柜内侧高压采样";
CM_ SG_ 2333212537 BAT_Pwr_57 "单柜实时功率";
CM_ SG_ 2333212537 S2A_SBMU_FaultClass_57 "SBMU故障等级";
CM_ SG_ 2333212537 ExtinguishingValve_Drive "灭火剂阀门驱动信号";
CM_ SG_ 2333212538 S2A_BAT_I_HVS_58 "电柜采集电流";
CM_ SG_ 2333212538 BAT_U_INNER_HVS_58 "电柜内侧高压采样";
CM_ SG_ 2333212538 BAT_Pwr_58 "单柜实时功率";
CM_ SG_ 2333212538 S2A_SBMU_FaultClass_58 "SBMU故障等级";
CM_ SG_ 2333212538 ExtinguishingValve_Drive "灭火剂阀门驱动信号";
CM_ SG_ 2333212539 S2A_BAT_I_HVS_59 "电柜采集电流";
CM_ SG_ 2333212539 BAT_U_INNER_HVS_59 "电柜内侧高压采样";
CM_ SG_ 2333212539 BAT_Pwr_59 "单柜实时功率";
CM_ SG_ 2333212539 S2A_SBMU_FaultClass_59 "SBMU故障等级";
CM_ SG_ 2333212539 ExtinguishingValve_Drive "灭火剂阀门驱动信号";
CM_ SG_ 2333212540 S2A_BAT_I_HVS_60 "电柜采集电流";
CM_ SG_ 2333212540 BAT_U_INNER_HVS_60 "电柜内侧高压采样";
CM_ SG_ 2333212540 BAT_Pwr_60 "单柜实时功率";
CM_ SG_ 2333212540 S2A_SBMU_FaultClass_60 "SBMU故障等级";
CM_ SG_ 2333212540 ExtinguishingValve_Drive "灭火剂阀门驱动信号";
CM_ SG_ 2333212541 S2A_BAT_I_HVS_61 "电柜采集电流";
CM_ SG_ 2333212541 BAT_U_INNER_HVS_61 "电柜内侧高压采样";
CM_ SG_ 2333212541 BAT_Pwr_61 "单柜实时功率";
CM_ SG_ 2333212541 S2A_SBMU_FaultClass_61 "SBMU故障等级";
CM_ SG_ 2333212541 ExtinguishingValve_Drive "灭火剂阀门驱动信号";
CM_ SG_ 2333212542 S2A_BAT_I_HVS_62 "电柜采集电流";
CM_ SG_ 2333212542 BAT_U_INNER_HVS_62 "电柜内侧高压采样";
CM_ SG_ 2333212542 BAT_Pwr_62 "单柜实时功率";
CM_ SG_ 2333212542 S2A_SBMU_FaultClass_62 "SBMU故障等级";
CM_ SG_ 2333212542 ExtinguishingValve_Drive "灭火剂阀门驱动信号";
CM_ SG_ 2333212543 S2A_BAT_I_HVS_63 "电柜采集电流";
CM_ SG_ 2333212543 BAT_U_INNER_HVS_63 "电柜内侧高压采样";
CM_ SG_ 2333212543 BAT_Pwr_63 "单柜实时功率";
CM_ SG_ 2333212543 S2A_SBMU_FaultClass_63 "SBMU故障等级";
CM_ SG_ 2333212543 ExtinguishingValve_Drive "灭火剂阀门驱动信号";
CM_ SG_ 2332688193 B2T_ControlMode_01 "BMS请求设定模式";
CM_ SG_ 2332688193 TMS_RunState_01 "TMS运行状态";
CM_ SG_ 2332688193 TMS_CommuFault_01 "TMS通信丢失";
CM_ SG_ 2332688193 TMS_ModeConflict_01 "TMS运行模式与BMS控制指令冲突";
CM_ SG_ 2332688193 TMS_MakeBMSStop_01 "TMS致电柜停机故障";
CM_ SG_ 2332688193 TMS_HVRealyState_01 "TMS高压继电器状态";
CM_ SG_ 2332688193 TMS_FaultCode_01 "TMS故障码";
CM_ SG_ 2332688193 TMS_FaultLevel_01 "TMS故障码等级";
CM_ SG_ 2332688193 B2T_TmptSetPoint_01 "BMS请求设定温度";
CM_ SG_ 2332688193 TMS_OutWaterTemp_01 "TMS出水温度";
CM_ SG_ 2332688193 TMS_BackWaterTemp_01 "TMS回水温度";
CM_ SG_ 2332688193 TMS_EnvTemp_01 "TMS环境温度";
CM_ SG_ 2332688193 TMS_RequestPower_01 "TMS需求功率";
CM_ SG_ 2332688193 STMS_ThrmStopReason_01 "热管理停机原因";
CM_ SG_ 2332688194 B2T_ControlMode_02 "BMS请求设定模式";
CM_ SG_ 2332688194 TMS_RunState_02 "TMS运行状态";
CM_ SG_ 2332688194 TMS_CommuFault_02 "TMS通信丢失";
CM_ SG_ 2332688194 TMS_ModeConflict_02 "TMS运行模式与BMS控制指令冲突";
CM_ SG_ 2332688194 TMS_MakeBMSStop_02 "TMS致电柜停机故障";
CM_ SG_ 2332688194 TMS_HVRealyState_02 "TMS高压继电器状态";
CM_ SG_ 2332688194 TMS_FaultCode_02 "TMS故障码";
CM_ SG_ 2332688194 TMS_FaultLevel_02 "TMS故障码等级";
CM_ SG_ 2332688194 B2T_TmptSetPoint_02 "BMS请求设定温度";
CM_ SG_ 2332688194 TMS_OutWaterTemp_02 "TMS出水温度";
CM_ SG_ 2332688194 TMS_BackWaterTemp_02 "TMS回水温度";
CM_ SG_ 2332688194 TMS_EnvTemp_02 "TMS环境温度";
CM_ SG_ 2332688194 TMS_RequestPower_02 "TMS需求功率";
CM_ SG_ 2332688194 STMS_ThrmStopReason_02 "热管理停机原因";
VAL_ 2332557153 Status_of_Closed_Loop 0 "关闭" 1 "开启" ;
VAL_ 2332557153 S2A_S7_FullDisChgFlgFromSBMU_33 1 "置位满放," 0 "未置位满放" ;
VAL_ 2332557153 S2A_S7_Reserved_33 65535 "Invalid" ;
VAL_ 2332557153 S2A_S7_SOH_33 65535 "Invalid" ;
VAL_ 2332557154 Status_of_Closed_Loop 0 "关闭" 1 "开启" ;
VAL_ 2332557154 S2A_S7_FullDisChgFlgFromSBMU_34 1 "置位满放," 0 "未置位满放" ;
VAL_ 2332557154 S2A_S7_Reserved_34 65535 "Invalid" ;
VAL_ 2332557154 S2A_S7_SOH_34 65535 "Invalid" ;
VAL_ 2332557155 Status_of_Closed_Loop 0 "关闭" 1 "开启" ;
VAL_ 2332557155 S2A_S7_FullDisChgFlgFromSBMU_35 1 "置位满放," 0 "未置位满放" ;
VAL_ 2332557155 S2A_S7_Reserved_35 65535 "Invalid" ;
VAL_ 2332557155 S2A_S7_SOH_35 65535 "Invalid" ;
VAL_ 2332557156 Status_of_Closed_Loop 0 "关闭" 1 "开启" ;
VAL_ 2332557156 S2A_S7_FullDisChgFlgFromSBMU_36 1 "置位满放," 0 "未置位满放" ;
VAL_ 2332557156 S2A_S7_Reserved_36 65535 "Invalid" ;
VAL_ 2332557156 S2A_S7_SOH_36 65535 "Invalid" ;
VAL_ 2332557157 Status_of_Closed_Loop 0 "关闭" 1 "开启" ;
VAL_ 2332557157 S2A_S7_FullDisChgFlgFromSBMU_37 1 "置位满放," 0 "未置位满放" ;
VAL_ 2332557157 S2A_S7_Reserved_37 65535 "Invalid" ;
VAL_ 2332557157 S2A_S7_SOH_37 65535 "Invalid" ;
VAL_ 2332557158 Status_of_Closed_Loop 0 "关闭" 1 "开启" ;
VAL_ 2332557158 S2A_S7_FullDisChgFlgFromSBMU_38 1 "置位满放," 0 "未置位满放" ;
VAL_ 2332557158 S2A_S7_Reserved_38 65535 "Invalid" ;
VAL_ 2332557158 S2A_S7_SOH_38 65535 "Invalid" ;
VAL_ 2332557159 Status_of_Closed_Loop 0 "关闭" 1 "开启" ;
VAL_ 2332557159 S2A_S7_FullDisChgFlgFromSBMU_39 1 "置位满放," 0 "未置位满放" ;
VAL_ 2332557159 S2A_S7_Reserved_39 65535 "Invalid" ;
VAL_ 2332557159 S2A_S7_SOH_39 65535 "Invalid" ;
VAL_ 2332557160 Status_of_Closed_Loop 0 "关闭" 1 "开启" ;
VAL_ 2332557160 S2A_S7_FullDisChgFlgFromSBMU_40 1 "置位满放," 0 "未置位满放" ;
VAL_ 2332557160 S2A_S7_Reserved_40 65535 "Invalid" ;
VAL_ 2332557160 S2A_S7_SOH_40 65535 "Invalid" ;
VAL_ 2332557161 Status_of_Closed_Loop 0 "关闭" 1 "开启" ;
VAL_ 2332557161 S2A_S7_FullDisChgFlgFromSBMU_41 1 "置位满放," 0 "未置位满放" ;
VAL_ 2332557161 S2A_S7_Reserved_41 65535 "Invalid" ;
VAL_ 2332557161 S2A_S7_SOH_41 65535 "Invalid" ;
VAL_ 2332557162 Status_of_Closed_Loop 0 "关闭" 1 "开启" ;
VAL_ 2332557162 S2A_S7_FullDisChgFlgFromSBMU_42 1 "置位满放," 0 "未置位满放" ;
VAL_ 2332557162 S2A_S7_Reserved_42 65535 "Invalid" ;
VAL_ 2332557162 S2A_S7_SOH_42 65535 "Invalid" ;
VAL_ 2332557163 Status_of_Closed_Loop 0 "关闭" 1 "开启" ;
VAL_ 2332557163 S2A_S7_FullDisChgFlgFromSBMU_43 1 "置位满放," 0 "未置位满放" ;
VAL_ 2332557163 S2A_S7_Reserved_43 65535 "Invalid" ;
VAL_ 2332557163 S2A_S7_SOH_43 65535 "Invalid" ;
VAL_ 2332557164 Status_of_Closed_Loop 0 "关闭" 1 "开启" ;
VAL_ 2332557164 S2A_S7_FullDisChgFlgFromSBMU_44 1 "置位满放," 0 "未置位满放" ;
VAL_ 2332557164 S2A_S7_Reserved_44 65535 "Invalid" ;
VAL_ 2332557164 S2A_S7_SOH_44 65535 "Invalid" ;
VAL_ 2332557165 Status_of_Closed_Loop 0 "关闭" 1 "开启" ;
VAL_ 2332557165 S2A_S7_FullDisChgFlgFromSBMU_45 1 "置位满放," 0 "未置位满放" ;
VAL_ 2332557165 S2A_S7_Reserved_45 65535 "Invalid" ;
VAL_ 2332557165 S2A_S7_SOH_45 65535 "Invalid" ;
VAL_ 2332557166 Status_of_Closed_Loop 0 "关闭" 1 "开启" ;
VAL_ 2332557166 S2A_S7_FullDisChgFlgFromSBMU_46 1 "置位满放," 0 "未置位满放" ;
VAL_ 2332557166 S2A_S7_Reserved_46 65535 "Invalid" ;
VAL_ 2332557166 S2A_S7_SOH_46 65535 "Invalid" ;
VAL_ 2332557167 Status_of_Closed_Loop 0 "关闭" 1 "开启" ;
VAL_ 2332557167 S2A_S7_FullDisChgFlgFromSBMU_47 1 "置位满放," 0 "未置位满放" ;
VAL_ 2332557167 S2A_S7_Reserved_47 65535 "Invalid" ;
VAL_ 2332557167 S2A_S7_SOH_47 65535 "Invalid" ;
VAL_ 2332557168 Status_of_Closed_Loop 0 "关闭" 1 "开启" ;
VAL_ 2332557168 S2A_S7_FullDisChgFlgFromSBMU_48 1 "置位满放," 0 "未置位满放" ;
VAL_ 2332557168 S2A_S7_Reserved_48 65535 "Invalid" ;
VAL_ 2332557168 S2A_S7_SOH_48 65535 "Invalid" ;
VAL_ 2332557169 Status_of_Closed_Loop 0 "关闭" 1 "开启" ;
VAL_ 2332557169 S2A_S7_FullDisChgFlgFromSBMU_49 1 "置位满放," 0 "未置位满放" ;
VAL_ 2332557169 S2A_S7_Reserved_49 65535 "Invalid" ;
VAL_ 2332557169 S2A_S7_SOH_49 65535 "Invalid" ;
VAL_ 2332557170 Status_of_Closed_Loop 0 "关闭" 1 "开启" ;
VAL_ 2332557170 S2A_S7_FullDisChgFlgFromSBMU_50 1 "置位满放," 0 "未置位满放" ;
VAL_ 2332557170 S2A_S7_Reserved_50 65535 "Invalid" ;
VAL_ 2332557170 S2A_S7_SOH_50 65535 "Invalid" ;
VAL_ 2332557171 Status_of_Closed_Loop 0 "关闭" 1 "开启" ;
VAL_ 2332557171 S2A_S7_FullDisChgFlgFromSBMU_51 1 "置位满放," 0 "未置位满放" ;
VAL_ 2332557171 S2A_S7_Reserved_51 65535 "Invalid" ;
VAL_ 2332557171 S2A_S7_SOH_51 65535 "Invalid" ;
VAL_ 2332557172 Status_of_Closed_Loop 0 "关闭" 1 "开启" ;
VAL_ 2332557172 S2A_S7_FullDisChgFlgFromSBMU_52 1 "置位满放," 0 "未置位满放" ;
VAL_ 2332557172 S2A_S7_Reserved_52 65535 "Invalid" ;
VAL_ 2332557172 S2A_S7_SOH_52 65535 "Invalid" ;
VAL_ 2332557173 Status_of_Closed_Loop 0 "关闭" 1 "开启" ;
VAL_ 2332557173 S2A_S7_FullDisChgFlgFromSBMU_53 1 "置位满放," 0 "未置位满放" ;
VAL_ 2332557173 S2A_S7_Reserved_53 65535 "Invalid" ;
VAL_ 2332557173 S2A_S7_SOH_53 65535 "Invalid" ;
VAL_ 2332557174 Status_of_Closed_Loop 0 "关闭" 1 "开启" ;
VAL_ 2332557174 S2A_S7_FullDisChgFlgFromSBMU_54 1 "置位满放," 0 "未置位满放" ;
VAL_ 2332557174 S2A_S7_Reserved_54 65535 "Invalid" ;
VAL_ 2332557174 S2A_S7_SOH_54 65535 "Invalid" ;
VAL_ 2332557175 Status_of_Closed_Loop 0 "关闭" 1 "开启" ;
VAL_ 2332557175 S2A_S7_FullDisChgFlgFromSBMU_55 1 "置位满放," 0 "未置位满放" ;
VAL_ 2332557175 S2A_S7_Reserved_55 65535 "Invalid" ;
VAL_ 2332557175 S2A_S7_SOH_55 65535 "Invalid" ;
VAL_ 2332557176 Status_of_Closed_Loop 0 "关闭" 1 "开启" ;
VAL_ 2332557176 S2A_S7_FullDisChgFlgFromSBMU_56 1 "置位满放," 0 "未置位满放" ;
VAL_ 2332557176 S2A_S7_Reserved_56 65535 "Invalid" ;
VAL_ 2332557176 S2A_S7_SOH_56 65535 "Invalid" ;
VAL_ 2332557177 Status_of_Closed_Loop 0 "关闭" 1 "开启" ;
VAL_ 2332557177 S2A_S7_FullDisChgFlgFromSBMU_57 1 "置位满放," 0 "未置位满放" ;
VAL_ 2332557177 S2A_S7_Reserved_57 65535 "Invalid" ;
VAL_ 2332557177 S2A_S7_SOH_57 65535 "Invalid" ;
VAL_ 2332557178 Status_of_Closed_Loop 0 "关闭" 1 "开启" ;
VAL_ 2332557178 S2A_S7_FullDisChgFlgFromSBMU_58 1 "置位满放," 0 "未置位满放" ;
VAL_ 2332557178 S2A_S7_Reserved_58 65535 "Invalid" ;
VAL_ 2332557178 S2A_S7_SOH_58 65535 "Invalid" ;
VAL_ 2332557179 Status_of_Closed_Loop 0 "关闭" 1 "开启" ;
VAL_ 2332557179 S2A_S7_FullDisChgFlgFromSBMU_59 1 "置位满放," 0 "未置位满放" ;
VAL_ 2332557179 S2A_S7_Reserved_59 65535 "Invalid" ;
VAL_ 2332557179 S2A_S7_SOH_59 65535 "Invalid" ;
VAL_ 2332557180 Status_of_Closed_Loop 0 "关闭" 1 "开启" ;
VAL_ 2332557180 S2A_S7_FullDisChgFlgFromSBMU_60 1 "置位满放," 0 "未置位满放" ;
VAL_ 2332557180 S2A_S7_Reserved_60 65535 "Invalid" ;
VAL_ 2332557180 S2A_S7_SOH_60 65535 "Invalid" ;
VAL_ 2332557181 Status_of_Closed_Loop 0 "关闭" 1 "开启" ;
VAL_ 2332557181 S2A_S7_FullDisChgFlgFromSBMU_61 1 "置位满放," 0 "未置位满放" ;
VAL_ 2332557181 S2A_S7_Reserved_61 65535 "Invalid" ;
VAL_ 2332557181 S2A_S7_SOH_61 65535 "Invalid" ;
VAL_ 2332557182 Status_of_Closed_Loop 0 "关闭" 1 "开启" ;
VAL_ 2332557182 S2A_S7_FullDisChgFlgFromSBMU_62 1 "置位满放," 0 "未置位满放" ;
VAL_ 2332557182 S2A_S7_Reserved_62 65535 "Invalid" ;
VAL_ 2332557182 S2A_S7_SOH_62 65535 "Invalid" ;
VAL_ 2332557183 Status_of_Closed_Loop 0 "关闭" 1 "开启" ;
VAL_ 2332557183 S2A_S7_FullDisChgFlgFromSBMU_63 1 "置位满放," 0 "未置位满放" ;
VAL_ 2332557183 S2A_S7_Reserved_63 65535 "Invalid" ;
VAL_ 2332557183 S2A_S7_SOH_63 65535 "Invalid" ;
VAL_ 2332622657 S2A_HIS_Charge_Engery_01 -2147483648 "Invalid" ;
VAL_ 2332622657 S2A_HIS_Discharge_Engery_01 -2147483648 "Invalid" ;
VAL_ 2332622658 S2A_HIS_Charge_Engery_02 -2147483648 "Invalid" ;
VAL_ 2332622658 S2A_HIS_Discharge_Engery_02 -2147483648 "Invalid" ;
VAL_ 2332622659 S2A_HIS_Charge_Engery_03 -2147483648 "Invalid" ;
VAL_ 2332622659 S2A_HIS_Discharge_Engery_03 -2147483648 "Invalid" ;
VAL_ 2332622660 S2A_HIS_Charge_Engery_04 -2147483648 "Invalid" ;
VAL_ 2332622660 S2A_HIS_Discharge_Engery_04 -2147483648 "Invalid" ;
VAL_ 2332622661 S2A_HIS_Charge_Engery_05 -2147483648 "Invalid" ;
VAL_ 2332622661 S2A_HIS_Discharge_Engery_05 -2147483648 "Invalid" ;
VAL_ 2332622662 S2A_HIS_Charge_Engery_06 -2147483648 "Invalid" ;
VAL_ 2332622662 S2A_HIS_Discharge_Engery_06 -2147483648 "Invalid" ;
VAL_ 2332622663 S2A_HIS_Charge_Engery_07 -2147483648 "Invalid" ;
VAL_ 2332622663 S2A_HIS_Discharge_Engery_07 -2147483648 "Invalid" ;
VAL_ 2332622664 S2A_HIS_Charge_Engery_08 -2147483648 "Invalid" ;
VAL_ 2332622664 S2A_HIS_Discharge_Engery_08 -2147483648 "Invalid" ;
VAL_ 2332622665 S2A_HIS_Charge_Engery_09 -2147483648 "Invalid" ;
VAL_ 2332622665 S2A_HIS_Discharge_Engery_09 -2147483648 "Invalid" ;
VAL_ 2332622666 S2A_HIS_Charge_Engery_10 -2147483648 "Invalid" ;
VAL_ 2332622666 S2A_HIS_Discharge_Engery_10 -2147483648 "Invalid" ;
VAL_ 2332622667 S2A_HIS_Charge_Engery_11 -2147483648 "Invalid" ;
VAL_ 2332622667 S2A_HIS_Discharge_Engery_11 -2147483648 "Invalid" ;
VAL_ 2332622668 S2A_HIS_Charge_Engery_12 -2147483648 "Invalid" ;
VAL_ 2332622668 S2A_HIS_Discharge_Engery_12 -2147483648 "Invalid" ;
VAL_ 2332622669 S2A_HIS_Charge_Engery_13 -2147483648 "Invalid" ;
VAL_ 2332622669 S2A_HIS_Discharge_Engery_13 -2147483648 "Invalid" ;
VAL_ 2332622670 S2A_HIS_Charge_Engery_14 -2147483648 "Invalid" ;
VAL_ 2332622670 S2A_HIS_Discharge_Engery_14 -2147483648 "Invalid" ;
VAL_ 2332622671 S2A_HIS_Charge_Engery_15 -2147483648 "Invalid" ;
VAL_ 2332622671 S2A_HIS_Discharge_Engery_15 -2147483648 "Invalid" ;
VAL_ 2332622672 S2A_HIS_Charge_Engery_16 -2147483648 "Invalid" ;
VAL_ 2332622672 S2A_HIS_Discharge_Engery_16 -2147483648 "Invalid" ;
VAL_ 2332622673 S2A_HIS_Charge_Engery_17 -2147483648 "Invalid" ;
VAL_ 2332622673 S2A_HIS_Discharge_Engery_17 -2147483648 "Invalid" ;
VAL_ 2332622674 S2A_HIS_Charge_Engery_18 -2147483648 "Invalid" ;
VAL_ 2332622674 S2A_HIS_Discharge_Engery_18 -2147483648 "Invalid" ;
VAL_ 2332622675 S2A_HIS_Charge_Engery_19 -2147483648 "Invalid" ;
VAL_ 2332622675 S2A_HIS_Discharge_Engery_19 -2147483648 "Invalid" ;
VAL_ 2332622676 S2A_HIS_Charge_Engery_20 -2147483648 "Invalid" ;
VAL_ 2332622676 S2A_HIS_Discharge_Engery_20 -2147483648 "Invalid" ;
VAL_ 2332622677 S2A_HIS_Charge_Engery_21 -2147483648 "Invalid" ;
VAL_ 2332622677 S2A_HIS_Discharge_Engery_21 -2147483648 "Invalid" ;
VAL_ 2332622678 S2A_HIS_Charge_Engery_22 -2147483648 "Invalid" ;
VAL_ 2332622678 S2A_HIS_Discharge_Engery_22 -2147483648 "Invalid" ;
VAL_ 2332622679 S2A_HIS_Charge_Engery_23 -2147483648 "Invalid" ;
VAL_ 2332622679 S2A_HIS_Discharge_Engery_23 -2147483648 "Invalid" ;
VAL_ 2332622680 S2A_HIS_Charge_Engery_24 -2147483648 "Invalid" ;
VAL_ 2332622680 S2A_HIS_Discharge_Engery_24 -2147483648 "Invalid" ;
VAL_ 2332622681 S2A_HIS_Charge_Engery_25 -2147483648 "Invalid" ;
VAL_ 2332622681 S2A_HIS_Discharge_Engery_25 -2147483648 "Invalid" ;
VAL_ 2332622682 S2A_HIS_Charge_Engery_26 -2147483648 "Invalid" ;
VAL_ 2332622682 S2A_HIS_Discharge_Engery_26 -2147483648 "Invalid" ;
VAL_ 2332622683 S2A_HIS_Charge_Engery_27 -2147483648 "Invalid" ;
VAL_ 2332622683 S2A_HIS_Discharge_Engery_27 -2147483648 "Invalid" ;
VAL_ 2332622684 S2A_HIS_Charge_Engery_28 -2147483648 "Invalid" ;
VAL_ 2332622684 S2A_HIS_Discharge_Engery_28 -2147483648 "Invalid" ;
VAL_ 2332622685 S2A_HIS_Charge_Engery_29 -2147483648 "Invalid" ;
VAL_ 2332622685 S2A_HIS_Discharge_Engery_29 -2147483648 "Invalid" ;
VAL_ 2332622686 S2A_HIS_Charge_Engery_30 -2147483648 "Invalid" ;
VAL_ 2332622686 S2A_HIS_Discharge_Engery_30 -2147483648 "Invalid" ;
VAL_ 2332622687 S2A_HIS_Charge_Engery_31 -2147483648 "Invalid" ;
VAL_ 2332622687 S2A_HIS_Discharge_Engery_31 -2147483648 "Invalid" ;
VAL_ 2332622688 S2A_HIS_Charge_Engery_32 -2147483648 "Invalid" ;
VAL_ 2332622688 S2A_HIS_Discharge_Engery_32 -2147483648 "Invalid" ;
VAL_ 2332622689 S2A_HIS_Charge_Engery_33 -2147483648 "Invalid" ;
VAL_ 2332622689 S2A_HIS_Discharge_Engery_33 -2147483648 "Invalid" ;
VAL_ 2332622690 S2A_HIS_Charge_Engery_34 -2147483648 "Invalid" ;
VAL_ 2332622690 S2A_HIS_Discharge_Engery_34 -2147483648 "Invalid" ;
VAL_ 2332622691 S2A_HIS_Charge_Engery_35 -2147483648 "Invalid" ;
VAL_ 2332622691 S2A_HIS_Discharge_Engery_35 -2147483648 "Invalid" ;
VAL_ 2332622692 S2A_HIS_Charge_Engery_36 -2147483648 "Invalid" ;
VAL_ 2332622692 S2A_HIS_Discharge_Engery_36 -2147483648 "Invalid" ;
VAL_ 2332622693 S2A_HIS_Charge_Engery_37 -2147483648 "Invalid" ;
VAL_ 2332622693 S2A_HIS_Discharge_Engery_37 -2147483648 "Invalid" ;
VAL_ 2332622694 S2A_HIS_Charge_Engery_38 -2147483648 "Invalid" ;
VAL_ 2332622694 S2A_HIS_Discharge_Engery_38 -2147483648 "Invalid" ;
VAL_ 2332622695 S2A_HIS_Charge_Engery_39 -2147483648 "Invalid" ;
VAL_ 2332622695 S2A_HIS_Discharge_Engery_39 -2147483648 "Invalid" ;
VAL_ 2332622696 S2A_HIS_Charge_Engery_40 -2147483648 "Invalid" ;
VAL_ 2332622696 S2A_HIS_Discharge_Engery_40 -2147483648 "Invalid" ;
VAL_ 2332622697 S2A_HIS_Charge_Engery_41 -2147483648 "Invalid" ;
VAL_ 2332622697 S2A_HIS_Discharge_Engery_41 -2147483648 "Invalid" ;
VAL_ 2332622698 S2A_HIS_Charge_Engery_42 -2147483648 "Invalid" ;
VAL_ 2332622698 S2A_HIS_Discharge_Engery_42 -2147483648 "Invalid" ;
VAL_ 2332622699 S2A_HIS_Charge_Engery_43 -2147483648 "Invalid" ;
VAL_ 2332622699 S2A_HIS_Discharge_Engery_43 -2147483648 "Invalid" ;
VAL_ 2332622700 S2A_HIS_Charge_Engery_44 -2147483648 "Invalid" ;
VAL_ 2332622700 S2A_HIS_Discharge_Engery_44 -2147483648 "Invalid" ;
VAL_ 2332622701 S2A_HIS_Charge_Engery_45 -2147483648 "Invalid" ;
VAL_ 2332622701 S2A_HIS_Discharge_Engery_45 -2147483648 "Invalid" ;
VAL_ 2332622702 S2A_HIS_Charge_Engery_46 -2147483648 "Invalid" ;
VAL_ 2332622702 S2A_HIS_Discharge_Engery_46 -2147483648 "Invalid" ;
VAL_ 2332622703 S2A_HIS_Charge_Engery_47 -2147483648 "Invalid" ;
VAL_ 2332622703 S2A_HIS_Discharge_Engery_47 -2147483648 "Invalid" ;
VAL_ 2332622704 S2A_HIS_Charge_Engery_48 -2147483648 "Invalid" ;
VAL_ 2332622704 S2A_HIS_Discharge_Engery_48 -2147483648 "Invalid" ;
VAL_ 2332622705 S2A_HIS_Charge_Engery_49 -2147483648 "Invalid" ;
VAL_ 2332622705 S2A_HIS_Discharge_Engery_49 -2147483648 "Invalid" ;
VAL_ 2332622706 S2A_HIS_Charge_Engery_50 -2147483648 "Invalid" ;
VAL_ 2332622706 S2A_HIS_Discharge_Engery_50 -2147483648 "Invalid" ;
VAL_ 2332622707 S2A_HIS_Charge_Engery_51 -2147483648 "Invalid" ;
VAL_ 2332622707 S2A_HIS_Discharge_Engery_51 -2147483648 "Invalid" ;
VAL_ 2332622708 S2A_HIS_Charge_Engery_52 -2147483648 "Invalid" ;
VAL_ 2332622708 S2A_HIS_Discharge_Engery_52 -2147483648 "Invalid" ;
VAL_ 2332622709 S2A_HIS_Charge_Engery_53 -2147483648 "Invalid" ;
VAL_ 2332622709 S2A_HIS_Discharge_Engery_53 -2147483648 "Invalid" ;
VAL_ 2332622710 S2A_HIS_Charge_Engery_54 -2147483648 "Invalid" ;
VAL_ 2332622710 S2A_HIS_Discharge_Engery_54 -2147483648 "Invalid" ;
VAL_ 2332622711 S2A_HIS_Charge_Engery_55 -2147483648 "Invalid" ;
VAL_ 2332622711 S2A_HIS_Discharge_Engery_55 -2147483648 "Invalid" ;
VAL_ 2332622712 S2A_HIS_Charge_Engery_56 -2147483648 "Invalid" ;
VAL_ 2332622712 S2A_HIS_Discharge_Engery_56 -2147483648 "Invalid" ;
VAL_ 2332622713 S2A_HIS_Charge_Engery_57 -2147483648 "Invalid" ;
VAL_ 2332622713 S2A_HIS_Discharge_Engery_57 -2147483648 "Invalid" ;
VAL_ 2332622714 S2A_HIS_Charge_Engery_58 -2147483648 "Invalid" ;
VAL_ 2332622714 S2A_HIS_Discharge_Engery_58 -2147483648 "Invalid" ;
VAL_ 2332622715 S2A_HIS_Charge_Engery_59 -2147483648 "Invalid" ;
VAL_ 2332622715 S2A_HIS_Discharge_Engery_59 -2147483648 "Invalid" ;
VAL_ 2332622716 S2A_HIS_Charge_Engery_60 -2147483648 "Invalid" ;
VAL_ 2332622716 S2A_HIS_Discharge_Engery_60 -2147483648 "Invalid" ;
VAL_ 2332622717 S2A_HIS_Charge_Engery_61 -2147483648 "Invalid" ;
VAL_ 2332622717 S2A_HIS_Discharge_Engery_61 -2147483648 "Invalid" ;
VAL_ 2332622718 S2A_HIS_Charge_Engery_62 -2147483648 "Invalid" ;
VAL_ 2332622718 S2A_HIS_Discharge_Engery_62 -2147483648 "Invalid" ;
VAL_ 2332622719 S2A_HIS_Charge_Engery_63 -2147483648 "Invalid" ;
VAL_ 2332622719 S2A_HIS_Discharge_Engery_63 -2147483648 "Invalid" ;
VAL_ 2332819265 S2A_NominalCellVol01 4095 "Invalid" ;
VAL_ 2332819265 S2A_Limit_CellChargeVol_01 4095 "Invalid" ;
VAL_ 2332819265 S2A_Limit_CellDisChargeVol_01 4095 "Invalid" ;
VAL_ 2332819265 S2A_Num_CellVoltSensors_Rack01 1023 "Invalid" ;
VAL_ 2332819266 S2A_NominalCellVol02 4095 "Invalid" ;
VAL_ 2332819266 S2A_Limit_CellChargeVol_02 4095 "Invalid" ;
VAL_ 2332819266 S2A_Limit_CellDisChargeVol_02 4095 "Invalid" ;
VAL_ 2332819266 S2A_Num_CellVoltSensors_Rack02 1023 "Invalid" ;
VAL_ 2332819267 S2A_NominalCellVol03 4095 "Invalid" ;
VAL_ 2332819267 S2A_Limit_CellChargeVol_03 4095 "Invalid" ;
VAL_ 2332819267 S2A_Limit_CellDisChargeVol_03 4095 "Invalid" ;
VAL_ 2332819267 S2A_Num_CellVoltSensors_Rack03 1023 "Invalid" ;
VAL_ 2332819268 S2A_NominalCellVol04 4095 "Invalid" ;
VAL_ 2332819268 S2A_Limit_CellChargeVol_04 4095 "Invalid" ;
VAL_ 2332819268 S2A_Limit_CellDisChargeVol_04 4095 "Invalid" ;
VAL_ 2332819268 S2A_Num_CellVoltSensors_Rack04 1023 "Invalid" ;
VAL_ 2332819269 S2A_NominalCellVol05 4095 "Invalid" ;
VAL_ 2332819269 S2A_Limit_CellChargeVol_05 4095 "Invalid" ;
VAL_ 2332819269 S2A_Limit_CellDisChargeVol_05 4095 "Invalid" ;
VAL_ 2332819269 S2A_Num_CellVoltSensors_Rack05 1023 "Invalid" ;
VAL_ 2332819270 S2A_NominalCellVol06 4095 "Invalid" ;
VAL_ 2332819270 S2A_Limit_CellChargeVol_06 4095 "Invalid" ;
VAL_ 2332819270 S2A_Limit_CellDisChargeVol_06 4095 "Invalid" ;
VAL_ 2332819270 S2A_Num_CellVoltSensors_Rack06 1023 "Invalid" ;
VAL_ 2332819271 S2A_NominalCellVol07 4095 "Invalid" ;
VAL_ 2332819271 S2A_Limit_CellChargeVol_07 4095 "Invalid" ;
VAL_ 2332819271 S2A_Limit_CellDisChargeVol_07 4095 "Invalid" ;
VAL_ 2332819271 S2A_Num_CellVoltSensors_Rack07 1023 "Invalid" ;
VAL_ 2332819272 S2A_NominalCellVol08 4095 "Invalid" ;
VAL_ 2332819272 S2A_Limit_CellChargeVol_08 4095 "Invalid" ;
VAL_ 2332819272 S2A_Limit_CellDisChargeVol_08 4095 "Invalid" ;
VAL_ 2332819272 S2A_Num_CellVoltSensors_Rack08 1023 "Invalid" ;
VAL_ 2332819273 S2A_NominalCellVol09 4095 "Invalid" ;
VAL_ 2332819273 S2A_Limit_CellChargeVol_09 4095 "Invalid" ;
VAL_ 2332819273 S2A_Limit_CellDisChargeVol_09 4095 "Invalid" ;
VAL_ 2332819273 S2A_Num_CellVoltSensors_Rack09 1023 "Invalid" ;
VAL_ 2332819274 S2A_NominalCellVol10 4095 "Invalid" ;
VAL_ 2332819274 S2A_Limit_CellChargeVol_10 4095 "Invalid" ;
VAL_ 2332819274 S2A_Limit_CellDisChargeVol_10 4095 "Invalid" ;
VAL_ 2332819274 S2A_Num_CellVoltSensors_Rack10 1023 "Invalid" ;
VAL_ 2332819275 S2A_NominalCellVol11 4095 "Invalid" ;
VAL_ 2332819275 S2A_Limit_CellChargeVol_11 4095 "Invalid" ;
VAL_ 2332819275 S2A_Limit_CellDisChargeVol_11 4095 "Invalid" ;
VAL_ 2332819275 S2A_Num_CellVoltSensors_Rack11 1023 "Invalid" ;
VAL_ 2332819276 S2A_NominalCellVol12 4095 "Invalid" ;
VAL_ 2332819276 S2A_Limit_CellChargeVol_12 4095 "Invalid" ;
VAL_ 2332819276 S2A_Limit_CellDisChargeVol_12 4095 "Invalid" ;
VAL_ 2332819276 S2A_Num_CellVoltSensors_Rack12 1023 "Invalid" ;
VAL_ 2332819277 S2A_NominalCellVol13 4095 "Invalid" ;
VAL_ 2332819277 S2A_Limit_CellChargeVol_13 4095 "Invalid" ;
VAL_ 2332819277 S2A_Limit_CellDisChargeVol_13 4095 "Invalid" ;
VAL_ 2332819277 S2A_Num_CellVoltSensors_Rack13 1023 "Invalid" ;
VAL_ 2332819278 S2A_NominalCellVol14 4095 "Invalid" ;
VAL_ 2332819278 S2A_Limit_CellChargeVol_14 4095 "Invalid" ;
VAL_ 2332819278 S2A_Limit_CellDisChargeVol_14 4095 "Invalid" ;
VAL_ 2332819278 S2A_Num_CellVoltSensors_Rack14 1023 "Invalid" ;
VAL_ 2332819279 S2A_NominalCellVol15 4095 "Invalid" ;
VAL_ 2332819279 S2A_Limit_CellChargeVol_15 4095 "Invalid" ;
VAL_ 2332819279 S2A_Limit_CellDisChargeVol_15 4095 "Invalid" ;
VAL_ 2332819279 S2A_Num_CellVoltSensors_Rack15 1023 "Invalid" ;
VAL_ 2332819280 S2A_NominalCellVol16 4095 "Invalid" ;
VAL_ 2332819280 S2A_Limit_CellChargeVol_16 4095 "Invalid" ;
VAL_ 2332819280 S2A_Limit_CellDisChargeVol_16 4095 "Invalid" ;
VAL_ 2332819280 S2A_Num_CellVoltSensors_Rack16 1023 "Invalid" ;
VAL_ 2332819281 S2A_NominalCellVol17 4095 "Invalid" ;
VAL_ 2332819281 S2A_Limit_CellChargeVol_17 4095 "Invalid" ;
VAL_ 2332819281 S2A_Limit_CellDisChargeVol_17 4095 "Invalid" ;
VAL_ 2332819281 S2A_Num_CellVoltSensors_Rack17 1023 "Invalid" ;
VAL_ 2332819282 S2A_NominalCellVol18 4095 "Invalid" ;
VAL_ 2332819282 S2A_Limit_CellChargeVol_18 4095 "Invalid" ;
VAL_ 2332819282 S2A_Limit_CellDisChargeVol_18 4095 "Invalid" ;
VAL_ 2332819282 S2A_Num_CellVoltSensors_Rack18 1023 "Invalid" ;
VAL_ 2332819283 S2A_NominalCellVol19 4095 "Invalid" ;
VAL_ 2332819283 S2A_Limit_CellChargeVol_19 4095 "Invalid" ;
VAL_ 2332819283 S2A_Limit_CellDisChargeVol_19 4095 "Invalid" ;
VAL_ 2332819283 S2A_Num_CellVoltSensors_Rack19 1023 "Invalid" ;
VAL_ 2332819284 S2A_NominalCellVol20 4095 "Invalid" ;
VAL_ 2332819284 S2A_Limit_CellChargeVol_20 4095 "Invalid" ;
VAL_ 2332819284 S2A_Limit_CellDisChargeVol_20 4095 "Invalid" ;
VAL_ 2332819284 S2A_Num_CellVoltSensors_Rack20 1023 "Invalid" ;
VAL_ 2332819285 S2A_NominalCellVol21 4095 "Invalid" ;
VAL_ 2332819285 S2A_Limit_CellChargeVol_21 4095 "Invalid" ;
VAL_ 2332819285 S2A_Limit_CellDisChargeVol_21 4095 "Invalid" ;
VAL_ 2332819285 S2A_Num_CellVoltSensors_Rack21 1023 "Invalid" ;
VAL_ 2332819286 S2A_NominalCellVol22 4095 "Invalid" ;
VAL_ 2332819286 S2A_Limit_CellChargeVol_22 4095 "Invalid" ;
VAL_ 2332819286 S2A_Limit_CellDisChargeVol_22 4095 "Invalid" ;
VAL_ 2332819286 S2A_Num_CellVoltSensors_Rack22 1023 "Invalid" ;
VAL_ 2332819287 S2A_NominalCellVol23 4095 "Invalid" ;
VAL_ 2332819287 S2A_Limit_CellChargeVol_23 4095 "Invalid" ;
VAL_ 2332819287 S2A_Limit_CellDisChargeVol_23 4095 "Invalid" ;
VAL_ 2332819287 S2A_Num_CellVoltSensors_Rack23 1023 "Invalid" ;
VAL_ 2332819288 S2A_NominalCellVol24 4095 "Invalid" ;
VAL_ 2332819288 S2A_Limit_CellChargeVol_24 4095 "Invalid" ;
VAL_ 2332819288 S2A_Limit_CellDisChargeVol_24 4095 "Invalid" ;
VAL_ 2332819288 S2A_Num_CellVoltSensors_Rack24 1023 "Invalid" ;
VAL_ 2332819289 S2A_NominalCellVol25 4095 "Invalid" ;
VAL_ 2332819289 S2A_Limit_CellChargeVol_25 4095 "Invalid" ;
VAL_ 2332819289 S2A_Limit_CellDisChargeVol_25 4095 "Invalid" ;
VAL_ 2332819289 S2A_Num_CellVoltSensors_Rack25 1023 "Invalid" ;
VAL_ 2332819290 S2A_NominalCellVol26 4095 "Invalid" ;
VAL_ 2332819290 S2A_Limit_CellChargeVol_26 4095 "Invalid" ;
VAL_ 2332819290 S2A_Limit_CellDisChargeVol_26 4095 "Invalid" ;
VAL_ 2332819290 S2A_Num_CellVoltSensors_Rack26 1023 "Invalid" ;
VAL_ 2332819291 S2A_NominalCellVol27 4095 "Invalid" ;
VAL_ 2332819291 S2A_Limit_CellChargeVol_27 4095 "Invalid" ;
VAL_ 2332819291 S2A_Limit_CellDisChargeVol_27 4095 "Invalid" ;
VAL_ 2332819291 S2A_Num_CellVoltSensors_Rack27 1023 "Invalid" ;
VAL_ 2332819292 S2A_NominalCellVol28 4095 "Invalid" ;
VAL_ 2332819292 S2A_Limit_CellChargeVol_28 4095 "Invalid" ;
VAL_ 2332819292 S2A_Limit_CellDisChargeVol_28 4095 "Invalid" ;
VAL_ 2332819292 S2A_Num_CellVoltSensors_Rack28 1023 "Invalid" ;
VAL_ 2332819293 S2A_NominalCellVol29 4095 "Invalid" ;
VAL_ 2332819293 S2A_Limit_CellChargeVol_29 4095 "Invalid" ;
VAL_ 2332819293 S2A_Limit_CellDisChargeVol_29 4095 "Invalid" ;
VAL_ 2332819293 S2A_Num_CellVoltSensors_Rack29 1023 "Invalid" ;
VAL_ 2332819294 S2A_NominalCellVol30 4095 "Invalid" ;
VAL_ 2332819294 S2A_Limit_CellChargeVol_30 4095 "Invalid" ;
VAL_ 2332819294 S2A_Limit_CellDisChargeVol_30 4095 "Invalid" ;
VAL_ 2332819294 S2A_Num_CellVoltSensors_Rack30 1023 "Invalid" ;
VAL_ 2332819295 S2A_NominalCellVol31 4095 "Invalid" ;
VAL_ 2332819295 S2A_Limit_CellChargeVol_31 4095 "Invalid" ;
VAL_ 2332819295 S2A_Limit_CellDisChargeVol_31 4095 "Invalid" ;
VAL_ 2332819295 S2A_Num_CellVoltSensors_Rack31 1023 "Invalid" ;
VAL_ 2332819296 S2A_NominalCellVol32 4095 "Invalid" ;
VAL_ 2332819296 S2A_Limit_CellChargeVol_32 4095 "Invalid" ;
VAL_ 2332819296 S2A_Limit_CellDisChargeVol_32 4095 "Invalid" ;
VAL_ 2332819296 S2A_Num_CellVoltSensors_Rack32 1023 "Invalid" ;
VAL_ 2332819297 S2A_NominalCellVol33 4095 "Invalid" ;
VAL_ 2332819297 S2A_Limit_CellChargeVol_33 4095 "Invalid" ;
VAL_ 2332819297 S2A_Limit_CellDisChargeVol_33 4095 "Invalid" ;
VAL_ 2332819297 S2A_Num_CellVoltSensors_Rack33 1023 "Invalid" ;
VAL_ 2332819298 S2A_NominalCellVol34 4095 "Invalid" ;
VAL_ 2332819298 S2A_Limit_CellChargeVol_34 4095 "Invalid" ;
VAL_ 2332819298 S2A_Limit_CellDisChargeVol_34 4095 "Invalid" ;
VAL_ 2332819298 S2A_Num_CellVoltSensors_Rack34 1023 "Invalid" ;
VAL_ 2332819299 S2A_NominalCellVol35 4095 "Invalid" ;
VAL_ 2332819299 S2A_Limit_CellChargeVol_35 4095 "Invalid" ;
VAL_ 2332819299 S2A_Limit_CellDisChargeVol_35 4095 "Invalid" ;
VAL_ 2332819299 S2A_Num_CellVoltSensors_Rack35 1023 "Invalid" ;
VAL_ 2332819300 S2A_NominalCellVol36 4095 "Invalid" ;
VAL_ 2332819300 S2A_Limit_CellChargeVol_36 4095 "Invalid" ;
VAL_ 2332819300 S2A_Limit_CellDisChargeVol_36 4095 "Invalid" ;
VAL_ 2332819300 S2A_Num_CellVoltSensors_Rack36 1023 "Invalid" ;
VAL_ 2332819301 S2A_NominalCellVol37 4095 "Invalid" ;
VAL_ 2332819301 S2A_Limit_CellChargeVol_37 4095 "Invalid" ;
VAL_ 2332819301 S2A_Limit_CellDisChargeVol_37 4095 "Invalid" ;
VAL_ 2332819301 S2A_Num_CellVoltSensors_Rack37 1023 "Invalid" ;
VAL_ 2332819302 S2A_NominalCellVol38 4095 "Invalid" ;
VAL_ 2332819302 S2A_Limit_CellChargeVol_38 4095 "Invalid" ;
VAL_ 2332819302 S2A_Limit_CellDisChargeVol_38 4095 "Invalid" ;
VAL_ 2332819302 S2A_Num_CellVoltSensors_Rack38 1023 "Invalid" ;
VAL_ 2332819303 S2A_NominalCellVol39 4095 "Invalid" ;
VAL_ 2332819303 S2A_Limit_CellChargeVol_39 4095 "Invalid" ;
VAL_ 2332819303 S2A_Limit_CellDisChargeVol_39 4095 "Invalid" ;
VAL_ 2332819303 S2A_Num_CellVoltSensors_Rack39 1023 "Invalid" ;
VAL_ 2332819304 S2A_NominalCellVol40 4095 "Invalid" ;
VAL_ 2332819304 S2A_Limit_CellChargeVol_40 4095 "Invalid" ;
VAL_ 2332819304 S2A_Limit_CellDisChargeVol_40 4095 "Invalid" ;
VAL_ 2332819304 S2A_Num_CellVoltSensors_Rack40 1023 "Invalid" ;
VAL_ 2332819305 S2A_NominalCellVol41 4095 "Invalid" ;
VAL_ 2332819305 S2A_Limit_CellChargeVol_41 4095 "Invalid" ;
VAL_ 2332819305 S2A_Limit_CellDisChargeVol_41 4095 "Invalid" ;
VAL_ 2332819305 S2A_Num_CellVoltSensors_Rack41 1023 "Invalid" ;
VAL_ 2332819306 S2A_NominalCellVol42 4095 "Invalid" ;
VAL_ 2332819306 S2A_Limit_CellChargeVol_42 4095 "Invalid" ;
VAL_ 2332819306 S2A_Limit_CellDisChargeVol_42 4095 "Invalid" ;
VAL_ 2332819306 S2A_Num_CellVoltSensors_Rack42 1023 "Invalid" ;
VAL_ 2332819307 S2A_NominalCellVol43 4095 "Invalid" ;
VAL_ 2332819307 S2A_Limit_CellChargeVol_43 4095 "Invalid" ;
VAL_ 2332819307 S2A_Limit_CellDisChargeVol_43 4095 "Invalid" ;
VAL_ 2332819307 S2A_Num_CellVoltSensors_Rack43 1023 "Invalid" ;
VAL_ 2332819308 S2A_NominalCellVol44 4095 "Invalid" ;
VAL_ 2332819308 S2A_Limit_CellChargeVol_44 4095 "Invalid" ;
VAL_ 2332819308 S2A_Limit_CellDisChargeVol_44 4095 "Invalid" ;
VAL_ 2332819308 S2A_Num_CellVoltSensors_Rack44 1023 "Invalid" ;
VAL_ 2332819309 S2A_NominalCellVol45 4095 "Invalid" ;
VAL_ 2332819309 S2A_Limit_CellChargeVol_45 4095 "Invalid" ;
VAL_ 2332819309 S2A_Limit_CellDisChargeVol_45 4095 "Invalid" ;
VAL_ 2332819309 S2A_Num_CellVoltSensors_Rack45 1023 "Invalid" ;
VAL_ 2332819310 S2A_NominalCellVol46 4095 "Invalid" ;
VAL_ 2332819310 S2A_Limit_CellChargeVol_46 4095 "Invalid" ;
VAL_ 2332819310 S2A_Limit_CellDisChargeVol_46 4095 "Invalid" ;
VAL_ 2332819310 S2A_Num_CellVoltSensors_Rack46 1023 "Invalid" ;
VAL_ 2332819311 S2A_NominalCellVol47 4095 "Invalid" ;
VAL_ 2332819311 S2A_Limit_CellChargeVol_47 4095 "Invalid" ;
VAL_ 2332819311 S2A_Limit_CellDisChargeVol_47 4095 "Invalid" ;
VAL_ 2332819311 S2A_Num_CellVoltSensors_Rack47 1023 "Invalid" ;
VAL_ 2332819312 S2A_NominalCellVol48 4095 "Invalid" ;
VAL_ 2332819312 S2A_Limit_CellChargeVol_48 4095 "Invalid" ;
VAL_ 2332819312 S2A_Limit_CellDisChargeVol_48 4095 "Invalid" ;
VAL_ 2332819312 S2A_Num_CellVoltSensors_Rack48 1023 "Invalid" ;
VAL_ 2332819313 S2A_NominalCellVol49 4095 "Invalid" ;
VAL_ 2332819313 S2A_Limit_CellChargeVol_49 4095 "Invalid" ;
VAL_ 2332819313 S2A_Limit_CellDisChargeVol_49 4095 "Invalid" ;
VAL_ 2332819313 S2A_Num_CellVoltSensors_Rack49 1023 "Invalid" ;
VAL_ 2332819314 S2A_NominalCellVol50 4095 "Invalid" ;
VAL_ 2332819314 S2A_Limit_CellChargeVol_50 4095 "Invalid" ;
VAL_ 2332819314 S2A_Limit_CellDisChargeVol_50 4095 "Invalid" ;
VAL_ 2332819314 S2A_Num_CellVoltSensors_Rack50 1023 "Invalid" ;
VAL_ 2332819315 S2A_NominalCellVol51 4095 "Invalid" ;
VAL_ 2332819315 S2A_Limit_CellChargeVol_51 4095 "Invalid" ;
VAL_ 2332819315 S2A_Limit_CellDisChargeVol_51 4095 "Invalid" ;
VAL_ 2332819315 S2A_Num_CellVoltSensors_Rack51 1023 "Invalid" ;
VAL_ 2332819316 S2A_NominalCellVol52 4095 "Invalid" ;
VAL_ 2332819316 S2A_Limit_CellChargeVol_52 4095 "Invalid" ;
VAL_ 2332819316 S2A_Limit_CellDisChargeVol_52 4095 "Invalid" ;
VAL_ 2332819316 S2A_Num_CellVoltSensors_Rack52 1023 "Invalid" ;
VAL_ 2332819317 S2A_NominalCellVol53 4095 "Invalid" ;
VAL_ 2332819317 S2A_Limit_CellChargeVol_53 4095 "Invalid" ;
VAL_ 2332819317 S2A_Limit_CellDisChargeVol_53 4095 "Invalid" ;
VAL_ 2332819317 S2A_Num_CellVoltSensors_Rack53 1023 "Invalid" ;
VAL_ 2332819318 S2A_NominalCellVol54 4095 "Invalid" ;
VAL_ 2332819318 S2A_Limit_CellChargeVol_54 4095 "Invalid" ;
VAL_ 2332819318 S2A_Limit_CellDisChargeVol_54 4095 "Invalid" ;
VAL_ 2332819318 S2A_Num_CellVoltSensors_Rack54 1023 "Invalid" ;
VAL_ 2332819319 S2A_NominalCellVol55 4095 "Invalid" ;
VAL_ 2332819319 S2A_Limit_CellChargeVol_55 4095 "Invalid" ;
VAL_ 2332819319 S2A_Limit_CellDisChargeVol_55 4095 "Invalid" ;
VAL_ 2332819319 S2A_Num_CellVoltSensors_Rack55 1023 "Invalid" ;
VAL_ 2332819320 S2A_NominalCellVol56 4095 "Invalid" ;
VAL_ 2332819320 S2A_Limit_CellChargeVol_56 4095 "Invalid" ;
VAL_ 2332819320 S2A_Limit_CellDisChargeVol_56 4095 "Invalid" ;
VAL_ 2332819320 S2A_Num_CellVoltSensors_Rack56 1023 "Invalid" ;
VAL_ 2332819321 S2A_NominalCellVol57 4095 "Invalid" ;
VAL_ 2332819321 S2A_Limit_CellChargeVol_57 4095 "Invalid" ;
VAL_ 2332819321 S2A_Limit_CellDisChargeVol_57 4095 "Invalid" ;
VAL_ 2332819321 S2A_Num_CellVoltSensors_Rack57 1023 "Invalid" ;
VAL_ 2332819322 S2A_NominalCellVol58 4095 "Invalid" ;
VAL_ 2332819322 S2A_Limit_CellChargeVol_58 4095 "Invalid" ;
VAL_ 2332819322 S2A_Limit_CellDisChargeVol_58 4095 "Invalid" ;
VAL_ 2332819322 S2A_Num_CellVoltSensors_Rack58 1023 "Invalid" ;
VAL_ 2332819323 S2A_NominalCellVol59 4095 "Invalid" ;
VAL_ 2332819323 S2A_Limit_CellChargeVol_59 4095 "Invalid" ;
VAL_ 2332819323 S2A_Limit_CellDisChargeVol_59 4095 "Invalid" ;
VAL_ 2332819323 S2A_Num_CellVoltSensors_Rack59 1023 "Invalid" ;
VAL_ 2332819324 S2A_NominalCellVol60 4095 "Invalid" ;
VAL_ 2332819324 S2A_Limit_CellChargeVol_60 4095 "Invalid" ;
VAL_ 2332819324 S2A_Limit_CellDisChargeVol_60 4095 "Invalid" ;
VAL_ 2332819324 S2A_Num_CellVoltSensors_Rack60 1023 "Invalid" ;
VAL_ 2332819325 S2A_NominalCellVol61 4095 "Invalid" ;
VAL_ 2332819325 S2A_Limit_CellChargeVol_61 4095 "Invalid" ;
VAL_ 2332819325 S2A_Limit_CellDisChargeVol_61 4095 "Invalid" ;
VAL_ 2332819325 S2A_Num_CellVoltSensors_Rack61 1023 "Invalid" ;
VAL_ 2332819326 S2A_NominalCellVol62 4095 "Invalid" ;
VAL_ 2332819326 S2A_Limit_CellChargeVol_62 4095 "Invalid" ;
VAL_ 2332819326 S2A_Limit_CellDisChargeVol_62 4095 "Invalid" ;
VAL_ 2332819326 S2A_Num_CellVoltSensors_Rack62 1023 "Invalid" ;
VAL_ 2332819327 S2A_NominalCellVol63 4095 "Invalid" ;
VAL_ 2332819327 S2A_Limit_CellChargeVol_63 4095 "Invalid" ;
VAL_ 2332819327 S2A_Limit_CellDisChargeVol_63 4095 "Invalid" ;
VAL_ 2332819327 S2A_Num_CellVoltSensors_Rack63 1023 "Invalid" ;
VAL_ 2333212481 S2A_SBMU_FaultClass_01 0 "无故障" 1 "1级故障" 2 "2级故障" 3 "3级故障" 4 "4级故障" 5 "5级故障" 6 "6级故障" 7 "7级故障" ;
VAL_ 2333212481 ExtinguishingValve_Drive 0 "不驱动" 1 "驱动" ;
VAL_ 2333212482 S2A_SBMU_FaultClass_02 0 "无故障" 1 "1级故障" 2 "2级故障" 3 "3级故障" 4 "4级故障" 5 "5级故障" 6 "6级故障" 7 "7级故障" ;
VAL_ 2333212482 ExtinguishingValve_Drive 0 "不驱动" 1 "驱动" ;
VAL_ 2333212483 S2A_SBMU_FaultClass_03 0 "无故障" 1 "1级故障" 2 "2级故障" 3 "3级故障" 4 "4级故障" 5 "5级故障" 6 "6级故障" 7 "7级故障" ;
VAL_ 2333212483 ExtinguishingValve_Drive 0 "不驱动" 1 "驱动" ;
VAL_ 2333212484 S2A_SBMU_FaultClass_04 0 "无故障" 1 "1级故障" 2 "2级故障" 3 "3级故障" 4 "4级故障" 5 "5级故障" 6 "6级故障" 7 "7级故障" ;
VAL_ 2333212484 ExtinguishingValve_Drive 0 "不驱动" 1 "驱动" ;
VAL_ 2333212485 S2A_SBMU_FaultClass_05 0 "无故障" 1 "1级故障" 2 "2级故障" 3 "3级故障" 4 "4级故障" 5 "5级故障" 6 "6级故障" 7 "7级故障" ;
VAL_ 2333212485 ExtinguishingValve_Drive 0 "不驱动" 1 "驱动" ;
VAL_ 2333212486 S2A_SBMU_FaultClass_06 0 "无故障" 1 "1级故障" 2 "2级故障" 3 "3级故障" 4 "4级故障" 5 "5级故障" 6 "6级故障" 7 "7级故障" ;
VAL_ 2333212486 ExtinguishingValve_Drive 0 "不驱动" 1 "驱动" ;
VAL_ 2333212487 S2A_SBMU_FaultClass_07 0 "无故障" 1 "1级故障" 2 "2级故障" 3 "3级故障" 4 "4级故障" 5 "5级故障" 6 "6级故障" 7 "7级故障" ;
VAL_ 2333212487 ExtinguishingValve_Drive 0 "不驱动" 1 "驱动" ;
VAL_ 2333212488 S2A_SBMU_FaultClass_08 0 "无故障" 1 "1级故障" 2 "2级故障" 3 "3级故障" 4 "4级故障" 5 "5级故障" 6 "6级故障" 7 "7级故障" ;
VAL_ 2333212488 ExtinguishingValve_Drive 0 "不驱动" 1 "驱动" ;
VAL_ 2333212489 S2A_SBMU_FaultClass_09 0 "无故障" 1 "1级故障" 2 "2级故障" 3 "3级故障" 4 "4级故障" 5 "5级故障" 6 "6级故障" 7 "7级故障" ;
VAL_ 2333212489 ExtinguishingValve_Drive 0 "不驱动" 1 "驱动" ;
VAL_ 2333212490 S2A_SBMU_FaultClass_10 0 "无故障" 1 "1级故障" 2 "2级故障" 3 "3级故障" 4 "4级故障" 5 "5级故障" 6 "6级故障" 7 "7级故障" ;
VAL_ 2333212490 ExtinguishingValve_Drive 0 "不驱动" 1 "驱动" ;
VAL_ 2333212491 S2A_SBMU_FaultClass_11 0 "无故障" 1 "1级故障" 2 "2级故障" 3 "3级故障" 4 "4级故障" 5 "5级故障" 6 "6级故障" 7 "7级故障" ;
VAL_ 2333212491 ExtinguishingValve_Drive 0 "不驱动" 1 "驱动" ;
VAL_ 2333212492 S2A_SBMU_FaultClass_12 0 "无故障" 1 "1级故障" 2 "2级故障" 3 "3级故障" 4 "4级故障" 5 "5级故障" 6 "6级故障" 7 "7级故障" ;
VAL_ 2333212492 ExtinguishingValve_Drive 0 "不驱动" 1 "驱动" ;
VAL_ 2333212493 S2A_SBMU_FaultClass_13 0 "无故障" 1 "1级故障" 2 "2级故障" 3 "3级故障" 4 "4级故障" 5 "5级故障" 6 "6级故障" 7 "7级故障" ;
VAL_ 2333212493 ExtinguishingValve_Drive 0 "不驱动" 1 "驱动" ;
VAL_ 2333212494 S2A_SBMU_FaultClass_14 0 "无故障" 1 "1级故障" 2 "2级故障" 3 "3级故障" 4 "4级故障" 5 "5级故障" 6 "6级故障" 7 "7级故障" ;
VAL_ 2333212494 ExtinguishingValve_Drive 0 "不驱动" 1 "驱动" ;
VAL_ 2333212495 S2A_SBMU_FaultClass_15 0 "无故障" 1 "1级故障" 2 "2级故障" 3 "3级故障" 4 "4级故障" 5 "5级故障" 6 "6级故障" 7 "7级故障" ;
VAL_ 2333212495 ExtinguishingValve_Drive 0 "不驱动" 1 "驱动" ;
VAL_ 2333212496 S2A_SBMU_FaultClass_16 0 "无故障" 1 "1级故障" 2 "2级故障" 3 "3级故障" 4 "4级故障" 5 "5级故障" 6 "6级故障" 7 "7级故障" ;
VAL_ 2333212496 ExtinguishingValve_Drive 0 "不驱动" 1 "驱动" ;
VAL_ 2333212497 S2A_SBMU_FaultClass_17 0 "无故障" 1 "1级故障" 2 "2级故障" 3 "3级故障" 4 "4级故障" 5 "5级故障" 6 "6级故障" 7 "7级故障" ;
VAL_ 2333212497 ExtinguishingValve_Drive 0 "不驱动" 1 "驱动" ;
VAL_ 2333212498 S2A_SBMU_FaultClass_18 0 "无故障" 1 "1级故障" 2 "2级故障" 3 "3级故障" 4 "4级故障" 5 "5级故障" 6 "6级故障" 7 "7级故障" ;
VAL_ 2333212498 ExtinguishingValve_Drive 0 "不驱动" 1 "驱动" ;
VAL_ 2333212499 S2A_SBMU_FaultClass_19 0 "无故障" 1 "1级故障" 2 "2级故障" 3 "3级故障" 4 "4级故障" 5 "5级故障" 6 "6级故障" 7 "7级故障" ;
VAL_ 2333212499 ExtinguishingValve_Drive 0 "不驱动" 1 "驱动" ;
VAL_ 2333212500 S2A_SBMU_FaultClass_20 0 "无故障" 1 "1级故障" 2 "2级故障" 3 "3级故障" 4 "4级故障" 5 "5级故障" 6 "6级故障" 7 "7级故障" ;
VAL_ 2333212500 ExtinguishingValve_Drive 0 "不驱动" 1 "驱动" ;
VAL_ 2333212501 S2A_SBMU_FaultClass_21 0 "无故障" 1 "1级故障" 2 "2级故障" 3 "3级故障" 4 "4级故障" 5 "5级故障" 6 "6级故障" 7 "7级故障" ;
VAL_ 2333212501 ExtinguishingValve_Drive 0 "不驱动" 1 "驱动" ;
VAL_ 2333212502 S2A_SBMU_FaultClass_22 0 "无故障" 1 "1级故障" 2 "2级故障" 3 "3级故障" 4 "4级故障" 5 "5级故障" 6 "6级故障" 7 "7级故障" ;
VAL_ 2333212502 ExtinguishingValve_Drive 0 "不驱动" 1 "驱动" ;
VAL_ 2333212503 S2A_SBMU_FaultClass_23 0 "无故障" 1 "1级故障" 2 "2级故障" 3 "3级故障" 4 "4级故障" 5 "5级故障" 6 "6级故障" 7 "7级故障" ;
VAL_ 2333212503 ExtinguishingValve_Drive 0 "不驱动" 1 "驱动" ;
VAL_ 2333212504 S2A_SBMU_FaultClass_24 0 "无故障" 1 "1级故障" 2 "2级故障" 3 "3级故障" 4 "4级故障" 5 "5级故障" 6 "6级故障" 7 "7级故障" ;
VAL_ 2333212504 ExtinguishingValve_Drive 0 "不驱动" 1 "驱动" ;
VAL_ 2333212505 S2A_SBMU_FaultClass_25 0 "无故障" 1 "1级故障" 2 "2级故障" 3 "3级故障" 4 "4级故障" 5 "5级故障" 6 "6级故障" 7 "7级故障" ;
VAL_ 2333212505 ExtinguishingValve_Drive 0 "不驱动" 1 "驱动" ;
VAL_ 2333212506 S2A_SBMU_FaultClass_26 0 "无故障" 1 "1级故障" 2 "2级故障" 3 "3级故障" 4 "4级故障" 5 "5级故障" 6 "6级故障" 7 "7级故障" ;
VAL_ 2333212506 ExtinguishingValve_Drive 0 "不驱动" 1 "驱动" ;
VAL_ 2333212507 S2A_SBMU_FaultClass_27 0 "无故障" 1 "1级故障" 2 "2级故障" 3 "3级故障" 4 "4级故障" 5 "5级故障" 6 "6级故障" 7 "7级故障" ;
VAL_ 2333212507 ExtinguishingValve_Drive 0 "不驱动" 1 "驱动" ;
VAL_ 2333212508 S2A_SBMU_FaultClass_28 0 "无故障" 1 "1级故障" 2 "2级故障" 3 "3级故障" 4 "4级故障" 5 "5级故障" 6 "6级故障" 7 "7级故障" ;
VAL_ 2333212508 ExtinguishingValve_Drive 0 "不驱动" 1 "驱动" ;
VAL_ 2333212509 S2A_SBMU_FaultClass_29 0 "无故障" 1 "1级故障" 2 "2级故障" 3 "3级故障" 4 "4级故障" 5 "5级故障" 6 "6级故障" 7 "7级故障" ;
VAL_ 2333212509 ExtinguishingValve_Drive 0 "不驱动" 1 "驱动" ;
VAL_ 2333212510 S2A_SBMU_FaultClass_30 0 "无故障" 1 "1级故障" 2 "2级故障" 3 "3级故障" 4 "4级故障" 5 "5级故障" 6 "6级故障" 7 "7级故障" ;
VAL_ 2333212510 ExtinguishingValve_Drive 0 "不驱动" 1 "驱动" ;
VAL_ 2333212511 S2A_SBMU_FaultClass_31 0 "无故障" 1 "1级故障" 2 "2级故障" 3 "3级故障" 4 "4级故障" 5 "5级故障" 6 "6级故障" 7 "7级故障" ;
VAL_ 2333212511 ExtinguishingValve_Drive 0 "不驱动" 1 "驱动" ;
VAL_ 2333212512 S2A_SBMU_FaultClass_32 0 "无故障" 1 "1级故障" 2 "2级故障" 3 "3级故障" 4 "4级故障" 5 "5级故障" 6 "6级故障" 7 "7级故障" ;
VAL_ 2333212512 ExtinguishingValve_Drive 0 "不驱动" 1 "驱动" ;
VAL_ 2333212513 S2A_SBMU_FaultClass_33 0 "无故障" 1 "1级故障" 2 "2级故障" 3 "3级故障" 4 "4级故障" 5 "5级故障" 6 "6级故障" 7 "7级故障" ;
VAL_ 2333212513 ExtinguishingValve_Drive 0 "不驱动" 1 "驱动" ;
VAL_ 2333212514 S2A_SBMU_FaultClass_34 0 "无故障" 1 "1级故障" 2 "2级故障" 3 "3级故障" 4 "4级故障" 5 "5级故障" 6 "6级故障" 7 "7级故障" ;
VAL_ 2333212514 ExtinguishingValve_Drive 0 "不驱动" 1 "驱动" ;
VAL_ 2333212515 S2A_SBMU_FaultClass_35 0 "无故障" 1 "1级故障" 2 "2级故障" 3 "3级故障" 4 "4级故障" 5 "5级故障" 6 "6级故障" 7 "7级故障" ;
VAL_ 2333212515 ExtinguishingValve_Drive 0 "不驱动" 1 "驱动" ;
VAL_ 2333212516 S2A_SBMU_FaultClass_36 0 "无故障" 1 "1级故障" 2 "2级故障" 3 "3级故障" 4 "4级故障" 5 "5级故障" 6 "6级故障" 7 "7级故障" ;
VAL_ 2333212516 ExtinguishingValve_Drive 0 "不驱动" 1 "驱动" ;
VAL_ 2333212517 S2A_SBMU_FaultClass_37 0 "无故障" 1 "1级故障" 2 "2级故障" 3 "3级故障" 4 "4级故障" 5 "5级故障" 6 "6级故障" 7 "7级故障" ;
VAL_ 2333212517 ExtinguishingValve_Drive 0 "不驱动" 1 "驱动" ;
VAL_ 2333212518 S2A_SBMU_FaultClass_38 0 "无故障" 1 "1级故障" 2 "2级故障" 3 "3级故障" 4 "4级故障" 5 "5级故障" 6 "6级故障" 7 "7级故障" ;
VAL_ 2333212518 ExtinguishingValve_Drive 0 "不驱动" 1 "驱动" ;
VAL_ 2333212519 S2A_SBMU_FaultClass_39 0 "无故障" 1 "1级故障" 2 "2级故障" 3 "3级故障" 4 "4级故障" 5 "5级故障" 6 "6级故障" 7 "7级故障" ;
VAL_ 2333212519 ExtinguishingValve_Drive 0 "不驱动" 1 "驱动" ;
VAL_ 2333212520 S2A_SBMU_FaultClass_40 0 "无故障" 1 "1级故障" 2 "2级故障" 3 "3级故障" 4 "4级故障" 5 "5级故障" 6 "6级故障" 7 "7级故障" ;
VAL_ 2333212520 ExtinguishingValve_Drive 0 "不驱动" 1 "驱动" ;
VAL_ 2333212521 S2A_SBMU_FaultClass_41 0 "无故障" 1 "1级故障" 2 "2级故障" 3 "3级故障" 4 "4级故障" 5 "5级故障" 6 "6级故障" 7 "7级故障" ;
VAL_ 2333212521 ExtinguishingValve_Drive 0 "不驱动" 1 "驱动" ;
VAL_ 2333212522 S2A_SBMU_FaultClass_42 0 "无故障" 1 "1级故障" 2 "2级故障" 3 "3级故障" 4 "4级故障" 5 "5级故障" 6 "6级故障" 7 "7级故障" ;
VAL_ 2333212522 ExtinguishingValve_Drive 0 "不驱动" 1 "驱动" ;
VAL_ 2333212523 S2A_SBMU_FaultClass_43 0 "无故障" 1 "1级故障" 2 "2级故障" 3 "3级故障" 4 "4级故障" 5 "5级故障" 6 "6级故障" 7 "7级故障" ;
VAL_ 2333212523 ExtinguishingValve_Drive 0 "不驱动" 1 "驱动" ;
VAL_ 2333212524 S2A_SBMU_FaultClass_44 0 "无故障" 1 "1级故障" 2 "2级故障" 3 "3级故障" 4 "4级故障" 5 "5级故障" 6 "6级故障" 7 "7级故障" ;
VAL_ 2333212524 ExtinguishingValve_Drive 0 "不驱动" 1 "驱动" ;
VAL_ 2333212525 S2A_SBMU_FaultClass_45 0 "无故障" 1 "1级故障" 2 "2级故障" 3 "3级故障" 4 "4级故障" 5 "5级故障" 6 "6级故障" 7 "7级故障" ;
VAL_ 2333212525 ExtinguishingValve_Drive 0 "不驱动" 1 "驱动" ;
VAL_ 2333212526 S2A_SBMU_FaultClass_46 0 "无故障" 1 "1级故障" 2 "2级故障" 3 "3级故障" 4 "4级故障" 5 "5级故障" 6 "6级故障" 7 "7级故障" ;
VAL_ 2333212526 ExtinguishingValve_Drive 0 "不驱动" 1 "驱动" ;
VAL_ 2333212527 S2A_SBMU_FaultClass_47 0 "无故障" 1 "1级故障" 2 "2级故障" 3 "3级故障" 4 "4级故障" 5 "5级故障" 6 "6级故障" 7 "7级故障" ;
VAL_ 2333212527 ExtinguishingValve_Drive 0 "不驱动" 1 "驱动" ;
VAL_ 2333212528 S2A_SBMU_FaultClass_48 0 "无故障" 1 "1级故障" 2 "2级故障" 3 "3级故障" 4 "4级故障" 5 "5级故障" 6 "6级故障" 7 "7级故障" ;
VAL_ 2333212528 ExtinguishingValve_Drive 0 "不驱动" 1 "驱动" ;
VAL_ 2333212529 S2A_SBMU_FaultClass_49 0 "无故障" 1 "1级故障" 2 "2级故障" 3 "3级故障" 4 "4级故障" 5 "5级故障" 6 "6级故障" 7 "7级故障" ;
VAL_ 2333212529 ExtinguishingValve_Drive 0 "不驱动" 1 "驱动" ;
VAL_ 2333212530 S2A_SBMU_FaultClass_50 0 "无故障" 1 "1级故障" 2 "2级故障" 3 "3级故障" 4 "4级故障" 5 "5级故障" 6 "6级故障" 7 "7级故障" ;
VAL_ 2333212530 ExtinguishingValve_Drive 0 "不驱动" 1 "驱动" ;
VAL_ 2333212531 S2A_SBMU_FaultClass_51 0 "无故障" 1 "1级故障" 2 "2级故障" 3 "3级故障" 4 "4级故障" 5 "5级故障" 6 "6级故障" 7 "7级故障" ;
VAL_ 2333212531 ExtinguishingValve_Drive 0 "不驱动" 1 "驱动" ;
VAL_ 2333212532 S2A_SBMU_FaultClass_52 0 "无故障" 1 "1级故障" 2 "2级故障" 3 "3级故障" 4 "4级故障" 5 "5级故障" 6 "6级故障" 7 "7级故障" ;
VAL_ 2333212532 ExtinguishingValve_Drive 0 "不驱动" 1 "驱动" ;
VAL_ 2333212533 S2A_SBMU_FaultClass_53 0 "无故障" 1 "1级故障" 2 "2级故障" 3 "3级故障" 4 "4级故障" 5 "5级故障" 6 "6级故障" 7 "7级故障" ;
VAL_ 2333212533 ExtinguishingValve_Drive 0 "不驱动" 1 "驱动" ;
VAL_ 2333212534 S2A_SBMU_FaultClass_54 0 "无故障" 1 "1级故障" 2 "2级故障" 3 "3级故障" 4 "4级故障" 5 "5级故障" 6 "6级故障" 7 "7级故障" ;
VAL_ 2333212534 ExtinguishingValve_Drive 0 "不驱动" 1 "驱动" ;
VAL_ 2333212535 S2A_SBMU_FaultClass_55 0 "无故障" 1 "1级故障" 2 "2级故障" 3 "3级故障" 4 "4级故障" 5 "5级故障" 6 "6级故障" 7 "7级故障" ;
VAL_ 2333212535 ExtinguishingValve_Drive 0 "不驱动" 1 "驱动" ;
VAL_ 2333212536 S2A_SBMU_FaultClass_56 0 "无故障" 1 "1级故障" 2 "2级故障" 3 "3级故障" 4 "4级故障" 5 "5级故障" 6 "6级故障" 7 "7级故障" ;
VAL_ 2333212536 ExtinguishingValve_Drive 0 "不驱动" 1 "驱动" ;
VAL_ 2333212537 S2A_SBMU_FaultClass_57 0 "无故障" 1 "1级故障" 2 "2级故障" 3 "3级故障" 4 "4级故障" 5 "5级故障" 6 "6级故障" 7 "7级故障" ;
VAL_ 2333212537 ExtinguishingValve_Drive 0 "不驱动" 1 "驱动" ;
VAL_ 2333212538 S2A_SBMU_FaultClass_58 0 "无故障" 1 "1级故障" 2 "2级故障" 3 "3级故障" 4 "4级故障" 5 "5级故障" 6 "6级故障" 7 "7级故障" ;
VAL_ 2333212538 ExtinguishingValve_Drive 0 "不驱动" 1 "驱动" ;
VAL_ 2333212539 S2A_SBMU_FaultClass_59 0 "无故障" 1 "1级故障" 2 "2级故障" 3 "3级故障" 4 "4级故障" 5 "5级故障" 6 "6级故障" 7 "7级故障" ;
VAL_ 2333212539 ExtinguishingValve_Drive 0 "不驱动" 1 "驱动" ;
VAL_ 2333212540 S2A_SBMU_FaultClass_60 0 "无故障" 1 "1级故障" 2 "2级故障" 3 "3级故障" 4 "4级故障" 5 "5级故障" 6 "6级故障" 7 "7级故障" ;
VAL_ 2333212540 ExtinguishingValve_Drive 0 "不驱动" 1 "驱动" ;
VAL_ 2333212541 S2A_SBMU_FaultClass_61 0 "无故障" 1 "1级故障" 2 "2级故障" 3 "3级故障" 4 "4级故障" 5 "5级故障" 6 "6级故障" 7 "7级故障" ;
VAL_ 2333212541 ExtinguishingValve_Drive 0 "不驱动" 1 "驱动" ;
VAL_ 2333212542 S2A_SBMU_FaultClass_62 0 "无故障" 1 "1级故障" 2 "2级故障" 3 "3级故障" 4 "4级故障" 5 "5级故障" 6 "6级故障" 7 "7级故障" ;
VAL_ 2333212542 ExtinguishingValve_Drive 0 "不驱动" 1 "驱动" ;
VAL_ 2333212543 S2A_SBMU_FaultClass_63 0 "无故障" 1 "1级故障" 2 "2级故障" 3 "3级故障" 4 "4级故障" 5 "5级故障" 6 "6级故障" 7 "7级故障" ;
VAL_ 2333212543 ExtinguishingValve_Drive 0 "不驱动" 1 "驱动" ;
VAL_ 2332688193 B2T_ControlMode_01 0 "关机模式" 1 "制冷模式" 2 "加热模式" 3 "自循环模式" ;
VAL_ 2332688193 TMS_RunState_01 0 "关机模式" 1 "制冷模式" 2 "加热模式" 3 "自循环模式" ;
VAL_ 2332688193 TMS_CommuFault_01 0 "无效" 1 "1级故障" ;
VAL_ 2332688193 TMS_ModeConflict_01 0 "无故障" 1 "故障" ;
VAL_ 2332688193 TMS_MakeBMSStop_01 0 "无故障" 1 "故障" ;
VAL_ 2332688193 TMS_HVRealyState_01 0 "断开状态" 1 "闭合状态" ;
VAL_ 2332688193 TMS_FaultCode_01 0 "无故障" ;
VAL_ 2332688193 TMS_FaultLevel_01 0 "无效" 1 "1级故障" 2 "2级故障" 3 "3级故障" ;
VAL_ 2332688193 B2T_TmptSetPoint_01 255 "Invalid" ;
VAL_ 2332688193 TMS_OutWaterTemp_01 255 "无效" ;
VAL_ 2332688193 TMS_BackWaterTemp_01 255 "无效" ;
VAL_ 2332688193 TMS_EnvTemp_01 255 "无效" ;
VAL_ 2332688193 TMS_RequestPower_01 65535 "无效" ;
VAL_ 2332688193 STMS_ThrmStopReason_01 0 "热管理正常停止" 1 "热管理由于其他模块故障停止" 2 "热管理由于热管理模块故障停止" ;
VAL_ 2332688194 B2T_ControlMode_02 0 "关机模式" 1 "制冷模式" 2 "加热模式" 3 "自循环模式" ;
VAL_ 2332688194 TMS_RunState_02 0 "关机模式" 1 "制冷模式" 2 "加热模式" 3 "自循环模式" ;
VAL_ 2332688194 TMS_CommuFault_02 0 "无效" 1 "1级故障" ;
VAL_ 2332688194 TMS_ModeConflict_02 0 "无故障" 1 "故障" ;
VAL_ 2332688194 TMS_MakeBMSStop_02 0 "无故障" 1 "故障" ;
VAL_ 2332688194 TMS_HVRealyState_02 0 "断开状态" 1 "闭合状态" ;
VAL_ 2332688194 TMS_FaultCode_02 0 "无故障" ;
VAL_ 2332688194 TMS_FaultLevel_02 0 "无效" 1 "1级故障" 2 "2级故障" 3 "3级故障" ;
VAL_ 2332688194 B2T_TmptSetPoint_02 255 "Invalid" ;
VAL_ 2332688194 TMS_OutWaterTemp_02 255 "无效" ;
VAL_ 2332688194 TMS_BackWaterTemp_02 255 "无效" ;
VAL_ 2332688194 TMS_EnvTemp_02 255 "无效" ;
VAL_ 2332688194 TMS_RequestPower_02 65535 "无效" ;
VAL_ 2332688194 STMS_ThrmStopReason_02 0 "热管理正常停止" 1 "热管理由于其他模块故障停止" 2 "热管理由于热管理模块故障停止" ;
VERSION ""

NS_ :

BS_:

BU_: MBMU PC SBMU IMM ETH DCDC LEMS

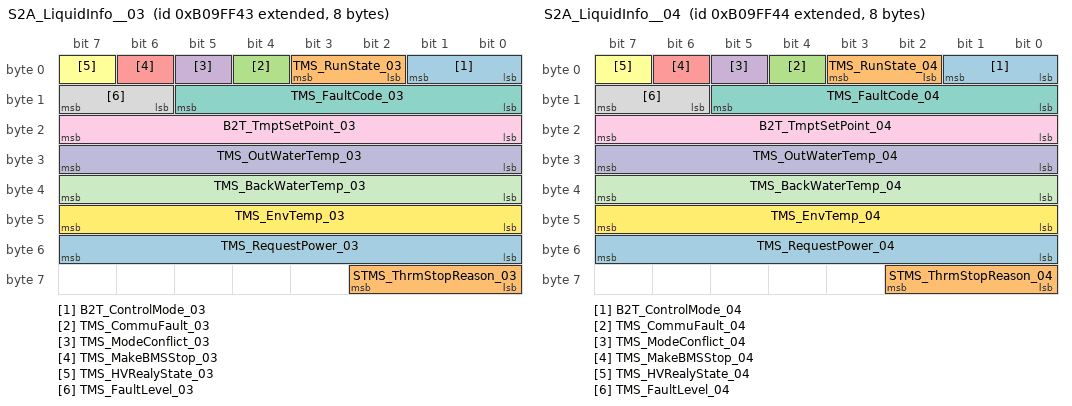
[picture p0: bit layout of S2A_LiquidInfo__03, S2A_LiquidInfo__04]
BO_ 2332688195 S2A_LiquidInfo__03: 8 SBMU
 SG_ B2T_ControlMode_03 : 0|2@1+ (1,0) [0|3] ""  MBMU,PC
 SG_ TMS_RunState_03 : 2|2@1+ (1,0) [0|3] ""  MBMU,PC
 SG_ TMS_CommuFault_03 : 4|1@1+ (1,0) [0|1] ""  MBMU,PC
 SG_ TMS_ModeConflict_03 : 5|1@1+ (1,0) [0|1] ""  MBMU,PC
 SG_ TMS_MakeBMSStop_03 : 6|1@1+ (1,0) [0|1] ""  MBMU,PC
 SG_ TMS_HVRealyState_03 : 7|1@1+ (1,0) [0|1] ""  MBMU,PC
 SG_ TMS_FaultCode_03 : 8|6@1+ (1,0) [0|63] ""  MBMU,PC
 SG_ TMS_FaultLevel_03 : 14|2@1+ (1,0) [0|3] ""  MBMU,PC
 SG_ B2T_TmptSetPoint_03 : 16|8@1+ (1,-50) [-50|210] "℃"  MBMU,PC
 SG_ TMS_OutWaterTemp_03 : 24|8@1+ (1,-50) [-50|210] "℃"  MBMU,PC
 SG_ TMS_BackWaterTemp_03 : 32|8@1+ (1,-50) [-50|210] "℃"  MBMU,PC
 SG_ TMS_EnvTemp_03 : 40|8@1+ (1,-50) [-50|210] "℃"  MBMU,PC
 SG_ TMS_RequestPower_03 : 48|8@1+ (0.1,0) [0|100] "Kw"  MBMU,PC
 SG_ STMS_ThrmStopReason_03 : 56|3@1+ (1,0) [0|3] ""  MBMU,PC

BO_ 2332688196 S2A_LiquidInfo__04: 8 SBMU
 SG_ B2T_ControlMode_04 : 0|2@1+ (1,0) [0|3] ""  MBMU,PC
 SG_ TMS_RunState_04 : 2|2@1+ (1,0) [0|3] ""  MBMU,PC
 SG_ TMS_CommuFault_04 : 4|1@1+ (1,0) [0|1] ""  MBMU,PC
 SG_ TMS_ModeConflict_04 : 5|1@1+ (1,0) [0|1] ""  MBMU,PC
 SG_ TMS_MakeBMSStop_04 : 6|1@1+ (1,0) [0|1] ""  MBMU,PC
 SG_ TMS_HVRealyState_04 : 7|1@1+ (1,0) [0|1] ""  MBMU,PC
 SG_ TMS_FaultCode_04 : 8|6@1+ (1,0) [0|63] ""  MBMU,PC
 SG_ TMS_FaultLevel_04 : 14|2@1+ (1,0) [0|3] ""  MBMU,PC
 SG_ B2T_TmptSetPoint_04 : 16|8@1+ (1,-50) [-50|210] "℃"  MBMU,PC
 SG_ TMS_OutWaterTemp_04 : 24|8@1+ (1,-50) [-50|210] "℃"  MBMU,PC
 SG_ TMS_BackWaterTemp_04 : 32|8@1+ (1,-50) [-50|210] "℃"  MBMU,PC
 SG_ TMS_EnvTemp_04 : 40|8@1+ (1,-50) [-50|210] "℃"  MBMU,PC
 SG_ TMS_RequestPower_04 : 48|8@1+ (0.1,0) [0|100] "Kw"  MBMU,PC
 SG_ STMS_ThrmStopReason_04 : 56|3@1+ (1,0) [0|3] ""  MBMU,PC

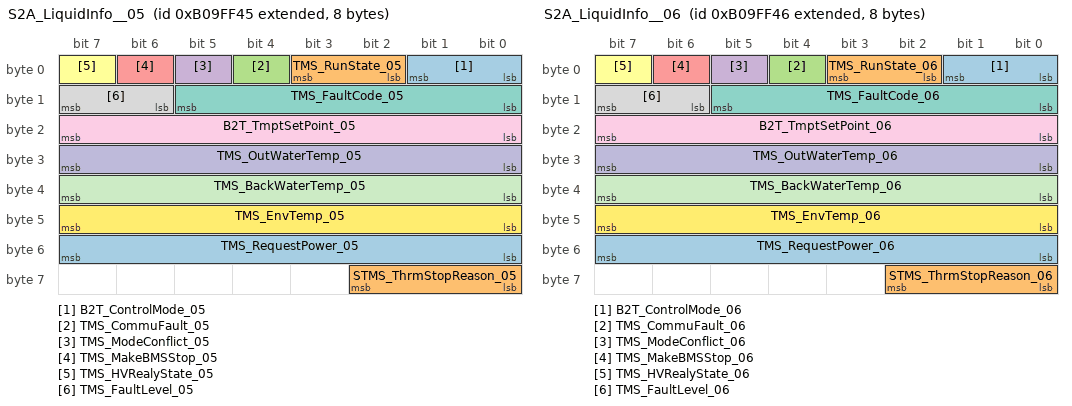
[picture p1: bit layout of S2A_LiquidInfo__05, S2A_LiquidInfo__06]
BO_ 2332688197 S2A_LiquidInfo__05: 8 SBMU
 SG_ B2T_ControlMode_05 : 0|2@1+ (1,0) [0|3] ""  MBMU,PC
 SG_ TMS_RunState_05 : 2|2@1+ (1,0) [0|3] ""  MBMU,PC
 SG_ TMS_CommuFault_05 : 4|1@1+ (1,0) [0|1] ""  MBMU,PC
 SG_ TMS_ModeConflict_05 : 5|1@1+ (1,0) [0|1] ""  MBMU,PC
 SG_ TMS_MakeBMSStop_05 : 6|1@1+ (1,0) [0|1] ""  MBMU,PC
 SG_ TMS_HVRealyState_05 : 7|1@1+ (1,0) [0|1] ""  MBMU,PC
 SG_ TMS_FaultCode_05 : 8|6@1+ (1,0) [0|63] ""  MBMU,PC
 SG_ TMS_FaultLevel_05 : 14|2@1+ (1,0) [0|3] ""  MBMU,PC
 SG_ B2T_TmptSetPoint_05 : 16|8@1+ (1,-50) [-50|210] "℃"  MBMU,PC
 SG_ TMS_OutWaterTemp_05 : 24|8@1+ (1,-50) [-50|210] "℃"  MBMU,PC
 SG_ TMS_BackWaterTemp_05 : 32|8@1+ (1,-50) [-50|210] "℃"  MBMU,PC
 SG_ TMS_EnvTemp_05 : 40|8@1+ (1,-50) [-50|210] "℃"  MBMU,PC
 SG_ TMS_RequestPower_05 : 48|8@1+ (0.1,0) [0|100] "Kw"  MBMU,PC
 SG_ STMS_ThrmStopReason_05 : 56|3@1+ (1,0) [0|3] ""  MBMU,PC

BO_ 2332688198 S2A_LiquidInfo__06: 8 SBMU
 SG_ B2T_ControlMode_06 : 0|2@1+ (1,0) [0|3] ""  MBMU,PC
 SG_ TMS_RunState_06 : 2|2@1+ (1,0) [0|3] ""  MBMU,PC
 SG_ TMS_CommuFault_06 : 4|1@1+ (1,0) [0|1] ""  MBMU,PC
 SG_ TMS_ModeConflict_06 : 5|1@1+ (1,0) [0|1] ""  MBMU,PC
 SG_ TMS_MakeBMSStop_06 : 6|1@1+ (1,0) [0|1] ""  MBMU,PC
 SG_ TMS_HVRealyState_06 : 7|1@1+ (1,0) [0|1] ""  MBMU,PC
 SG_ TMS_FaultCode_06 : 8|6@1+ (1,0) [0|63] ""  MBMU,PC
 SG_ TMS_FaultLevel_06 : 14|2@1+ (1,0) [0|3] ""  MBMU,PC
 SG_ B2T_TmptSetPoint_06 : 16|8@1+ (1,-50) [-50|210] "℃"  MBMU,PC
 SG_ TMS_OutWaterTemp_06 : 24|8@1+ (1,-50) [-50|210] "℃"  MBMU,PC
 SG_ TMS_BackWaterTemp_06 : 32|8@1+ (1,-50) [-50|210] "℃"  MBMU,PC
 SG_ TMS_EnvTemp_06 : 40|8@1+ (1,-50) [-50|210] "℃"  MBMU,PC
 SG_ TMS_RequestPower_06 : 48|8@1+ (0.1,0) [0|100] "Kw"  MBMU,PC
 SG_ STMS_ThrmStopReason_06 : 56|3@1+ (1,0) [0|3] ""  MBMU,PC

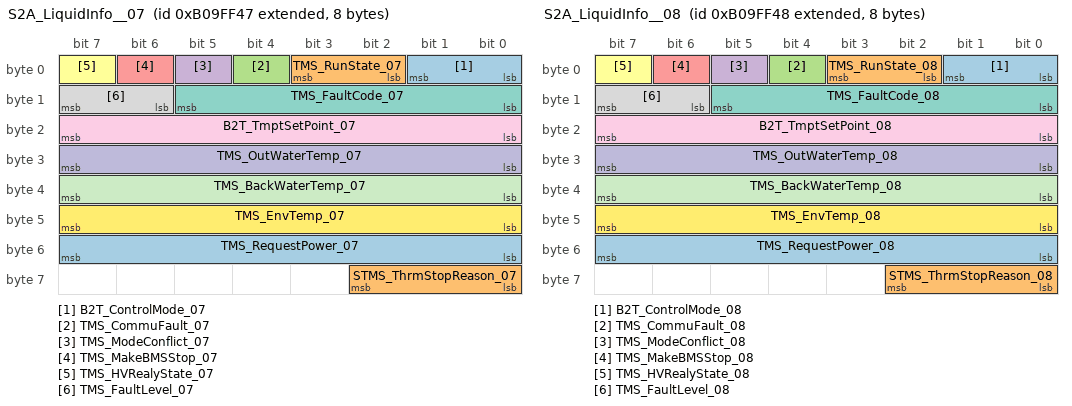
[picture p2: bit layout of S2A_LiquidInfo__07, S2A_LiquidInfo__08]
BO_ 2332688199 S2A_LiquidInfo__07: 8 SBMU
 SG_ B2T_ControlMode_07 : 0|2@1+ (1,0) [0|3] ""  MBMU,PC
 SG_ TMS_RunState_07 : 2|2@1+ (1,0) [0|3] ""  MBMU,PC
 SG_ TMS_CommuFault_07 : 4|1@1+ (1,0) [0|1] ""  MBMU,PC
 SG_ TMS_ModeConflict_07 : 5|1@1+ (1,0) [0|1] ""  MBMU,PC
 SG_ TMS_MakeBMSStop_07 : 6|1@1+ (1,0) [0|1] ""  MBMU,PC
 SG_ TMS_HVRealyState_07 : 7|1@1+ (1,0) [0|1] ""  MBMU,PC
 SG_ TMS_FaultCode_07 : 8|6@1+ (1,0) [0|63] ""  MBMU,PC
 SG_ TMS_FaultLevel_07 : 14|2@1+ (1,0) [0|3] ""  MBMU,PC
 SG_ B2T_TmptSetPoint_07 : 16|8@1+ (1,-50) [-50|210] "℃"  MBMU,PC
 SG_ TMS_OutWaterTemp_07 : 24|8@1+ (1,-50) [-50|210] "℃"  MBMU,PC
 SG_ TMS_BackWaterTemp_07 : 32|8@1+ (1,-50) [-50|210] "℃"  MBMU,PC
 SG_ TMS_EnvTemp_07 : 40|8@1+ (1,-50) [-50|210] "℃"  MBMU,PC
 SG_ TMS_RequestPower_07 : 48|8@1+ (0.1,0) [0|100] "Kw"  MBMU,PC
 SG_ STMS_ThrmStopReason_07 : 56|3@1+ (1,0) [0|3] ""  MBMU,PC

BO_ 2332688200 S2A_LiquidInfo__08: 8 SBMU
 SG_ B2T_ControlMode_08 : 0|2@1+ (1,0) [0|3] ""  MBMU,PC
 SG_ TMS_RunState_08 : 2|2@1+ (1,0) [0|3] ""  MBMU,PC
 SG_ TMS_CommuFault_08 : 4|1@1+ (1,0) [0|1] ""  MBMU,PC
 SG_ TMS_ModeConflict_08 : 5|1@1+ (1,0) [0|1] ""  MBMU,PC
 SG_ TMS_MakeBMSStop_08 : 6|1@1+ (1,0) [0|1] ""  MBMU,PC
 SG_ TMS_HVRealyState_08 : 7|1@1+ (1,0) [0|1] ""  MBMU,PC
 SG_ TMS_FaultCode_08 : 8|6@1+ (1,0) [0|63] ""  MBMU,PC
 SG_ TMS_FaultLevel_08 : 14|2@1+ (1,0) [0|3] ""  MBMU,PC
 SG_ B2T_TmptSetPoint_08 : 16|8@1+ (1,-50) [-50|210] "℃"  MBMU,PC
 SG_ TMS_OutWaterTemp_08 : 24|8@1+ (1,-50) [-50|210] "℃"  MBMU,PC
 SG_ TMS_BackWaterTemp_08 : 32|8@1+ (1,-50) [-50|210] "℃"  MBMU,PC
 SG_ TMS_EnvTemp_08 : 40|8@1+ (1,-50) [-50|210] "℃"  MBMU,PC
 SG_ TMS_RequestPower_08 : 48|8@1+ (0.1,0) [0|100] "Kw"  MBMU,PC
 SG_ STMS_ThrmStopReason_08 : 56|3@1+ (1,0) [0|3] ""  MBMU,PC

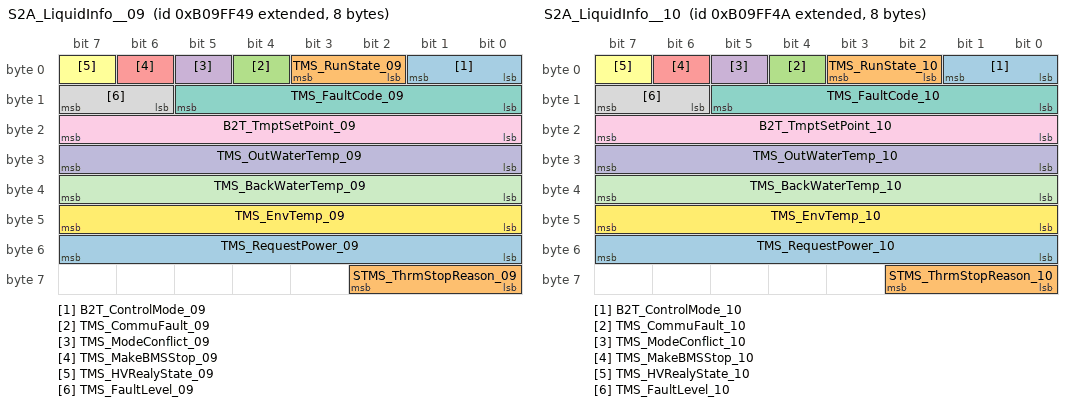
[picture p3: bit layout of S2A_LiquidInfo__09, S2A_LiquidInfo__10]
BO_ 2332688201 S2A_LiquidInfo__09: 8 SBMU
 SG_ B2T_ControlMode_09 : 0|2@1+ (1,0) [0|3] ""  MBMU,PC
 SG_ TMS_RunState_09 : 2|2@1+ (1,0) [0|3] ""  MBMU,PC
 SG_ TMS_CommuFault_09 : 4|1@1+ (1,0) [0|1] ""  MBMU,PC
 SG_ TMS_ModeConflict_09 : 5|1@1+ (1,0) [0|1] ""  MBMU,PC
 SG_ TMS_MakeBMSStop_09 : 6|1@1+ (1,0) [0|1] ""  MBMU,PC
 SG_ TMS_HVRealyState_09 : 7|1@1+ (1,0) [0|1] ""  MBMU,PC
 SG_ TMS_FaultCode_09 : 8|6@1+ (1,0) [0|63] ""  MBMU,PC
 SG_ TMS_FaultLevel_09 : 14|2@1+ (1,0) [0|3] ""  MBMU,PC
 SG_ B2T_TmptSetPoint_09 : 16|8@1+ (1,-50) [-50|210] "℃"  MBMU,PC
 SG_ TMS_OutWaterTemp_09 : 24|8@1+ (1,-50) [-50|210] "℃"  MBMU,PC
 SG_ TMS_BackWaterTemp_09 : 32|8@1+ (1,-50) [-50|210] "℃"  MBMU,PC
 SG_ TMS_EnvTemp_09 : 40|8@1+ (1,-50) [-50|210] "℃"  MBMU,PC
 SG_ TMS_RequestPower_09 : 48|8@1+ (0.1,0) [0|100] "Kw"  MBMU,PC
 SG_ STMS_ThrmStopReason_09 : 56|3@1+ (1,0) [0|3] ""  MBMU,PC

BO_ 2332688202 S2A_LiquidInfo__10: 8 SBMU
 SG_ B2T_ControlMode_10 : 0|2@1+ (1,0) [0|3] ""  MBMU,PC
 SG_ TMS_RunState_10 : 2|2@1+ (1,0) [0|3] ""  MBMU,PC
 SG_ TMS_CommuFault_10 : 4|1@1+ (1,0) [0|1] ""  MBMU,PC
 SG_ TMS_ModeConflict_10 : 5|1@1+ (1,0) [0|1] ""  MBMU,PC
 SG_ TMS_MakeBMSStop_10 : 6|1@1+ (1,0) [0|1] ""  MBMU,PC
 SG_ TMS_HVRealyState_10 : 7|1@1+ (1,0) [0|1] ""  MBMU,PC
 SG_ TMS_FaultCode_10 : 8|6@1+ (1,0) [0|63] ""  MBMU,PC
 SG_ TMS_FaultLevel_10 : 14|2@1+ (1,0) [0|3] ""  MBMU,PC
 SG_ B2T_TmptSetPoint_10 : 16|8@1+ (1,-50) [-50|210] "℃"  MBMU,PC
 SG_ TMS_OutWaterTemp_10 : 24|8@1+ (1,-50) [-50|210] "℃"  MBMU,PC
 SG_ TMS_BackWaterTemp_10 : 32|8@1+ (1,-50) [-50|210] "℃"  MBMU,PC
 SG_ TMS_EnvTemp_10 : 40|8@1+ (1,-50) [-50|210] "℃"  MBMU,PC
 SG_ TMS_RequestPower_10 : 48|8@1+ (0.1,0) [0|100] "Kw"  MBMU,PC
 SG_ STMS_ThrmStopReason_10 : 56|3@1+ (1,0) [0|3] ""  MBMU,PC

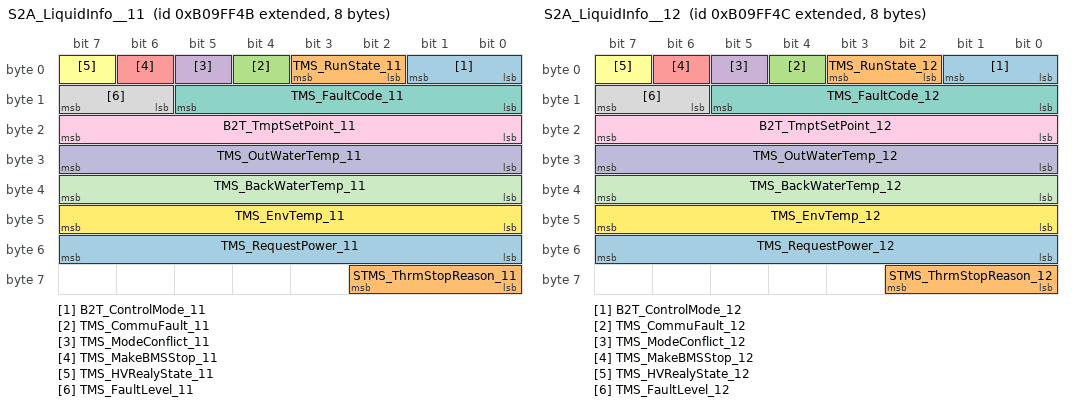
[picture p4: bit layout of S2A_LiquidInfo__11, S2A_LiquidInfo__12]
BO_ 2332688203 S2A_LiquidInfo__11: 8 SBMU
 SG_ B2T_ControlMode_11 : 0|2@1+ (1,0) [0|3] ""  MBMU,PC
 SG_ TMS_RunState_11 : 2|2@1+ (1,0) [0|3] ""  MBMU,PC
 SG_ TMS_CommuFault_11 : 4|1@1+ (1,0) [0|1] ""  MBMU,PC
 SG_ TMS_ModeConflict_11 : 5|1@1+ (1,0) [0|1] ""  MBMU,PC
 SG_ TMS_MakeBMSStop_11 : 6|1@1+ (1,0) [0|1] ""  MBMU,PC
 SG_ TMS_HVRealyState_11 : 7|1@1+ (1,0) [0|1] ""  MBMU,PC
 SG_ TMS_FaultCode_11 : 8|6@1+ (1,0) [0|63] ""  MBMU,PC
 SG_ TMS_FaultLevel_11 : 14|2@1+ (1,0) [0|3] ""  MBMU,PC
 SG_ B2T_TmptSetPoint_11 : 16|8@1+ (1,-50) [-50|210] "℃"  MBMU,PC
 SG_ TMS_OutWaterTemp_11 : 24|8@1+ (1,-50) [-50|210] "℃"  MBMU,PC
 SG_ TMS_BackWaterTemp_11 : 32|8@1+ (1,-50) [-50|210] "℃"  MBMU,PC
 SG_ TMS_EnvTemp_11 : 40|8@1+ (1,-50) [-50|210] "℃"  MBMU,PC
 SG_ TMS_RequestPower_11 : 48|8@1+ (0.1,0) [0|100] "Kw"  MBMU,PC
 SG_ STMS_ThrmStopReason_11 : 56|3@1+ (1,0) [0|3] ""  MBMU,PC

BO_ 2332688204 S2A_LiquidInfo__12: 8 SBMU
 SG_ B2T_ControlMode_12 : 0|2@1+ (1,0) [0|3] ""  MBMU,PC
 SG_ TMS_RunState_12 : 2|2@1+ (1,0) [0|3] ""  MBMU,PC
 SG_ TMS_CommuFault_12 : 4|1@1+ (1,0) [0|1] ""  MBMU,PC
 SG_ TMS_ModeConflict_12 : 5|1@1+ (1,0) [0|1] ""  MBMU,PC
 SG_ TMS_MakeBMSStop_12 : 6|1@1+ (1,0) [0|1] ""  MBMU,PC
 SG_ TMS_HVRealyState_12 : 7|1@1+ (1,0) [0|1] ""  MBMU,PC
 SG_ TMS_FaultCode_12 : 8|6@1+ (1,0) [0|63] ""  MBMU,PC
 SG_ TMS_FaultLevel_12 : 14|2@1+ (1,0) [0|3] ""  MBMU,PC
 SG_ B2T_TmptSetPoint_12 : 16|8@1+ (1,-50) [-50|210] "℃"  MBMU,PC
 SG_ TMS_OutWaterTemp_12 : 24|8@1+ (1,-50) [-50|210] "℃"  MBMU,PC
 SG_ TMS_BackWaterTemp_12 : 32|8@1+ (1,-50) [-50|210] "℃"  MBMU,PC
 SG_ TMS_EnvTemp_12 : 40|8@1+ (1,-50) [-50|210] "℃"  MBMU,PC
 SG_ TMS_RequestPower_12 : 48|8@1+ (0.1,0) [0|100] "Kw"  MBMU,PC
 SG_ STMS_ThrmStopReason_12 : 56|3@1+ (1,0) [0|3] ""  MBMU,PC

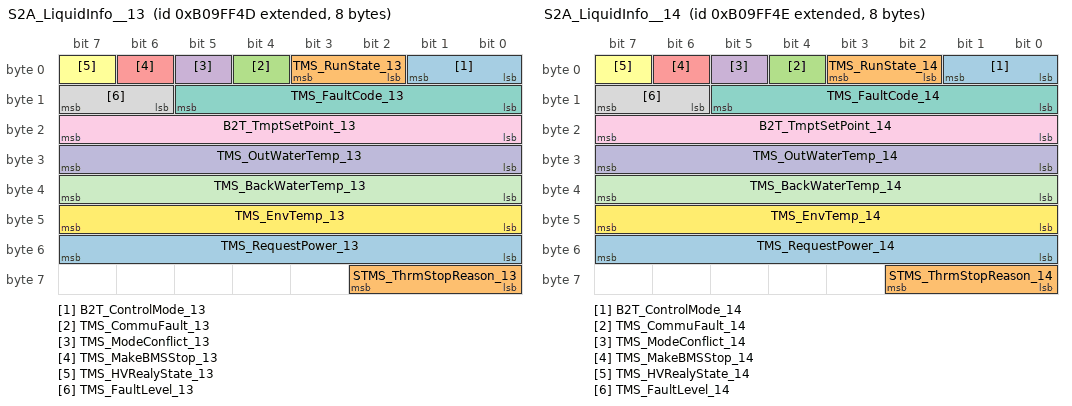
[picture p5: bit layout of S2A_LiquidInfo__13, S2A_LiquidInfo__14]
BO_ 2332688205 S2A_LiquidInfo__13: 8 SBMU
 SG_ B2T_ControlMode_13 : 0|2@1+ (1,0) [0|3] ""  MBMU,PC
 SG_ TMS_RunState_13 : 2|2@1+ (1,0) [0|3] ""  MBMU,PC
 SG_ TMS_CommuFault_13 : 4|1@1+ (1,0) [0|1] ""  MBMU,PC
 SG_ TMS_ModeConflict_13 : 5|1@1+ (1,0) [0|1] ""  MBMU,PC
 SG_ TMS_MakeBMSStop_13 : 6|1@1+ (1,0) [0|1] ""  MBMU,PC
 SG_ TMS_HVRealyState_13 : 7|1@1+ (1,0) [0|1] ""  MBMU,PC
 SG_ TMS_FaultCode_13 : 8|6@1+ (1,0) [0|63] ""  MBMU,PC
 SG_ TMS_FaultLevel_13 : 14|2@1+ (1,0) [0|3] ""  MBMU,PC
 SG_ B2T_TmptSetPoint_13 : 16|8@1+ (1,-50) [-50|210] "℃"  MBMU,PC
 SG_ TMS_OutWaterTemp_13 : 24|8@1+ (1,-50) [-50|210] "℃"  MBMU,PC
 SG_ TMS_BackWaterTemp_13 : 32|8@1+ (1,-50) [-50|210] "℃"  MBMU,PC
 SG_ TMS_EnvTemp_13 : 40|8@1+ (1,-50) [-50|210] "℃"  MBMU,PC
 SG_ TMS_RequestPower_13 : 48|8@1+ (0.1,0) [0|100] "Kw"  MBMU,PC
 SG_ STMS_ThrmStopReason_13 : 56|3@1+ (1,0) [0|3] ""  MBMU,PC

BO_ 2332688206 S2A_LiquidInfo__14: 8 SBMU
 SG_ B2T_ControlMode_14 : 0|2@1+ (1,0) [0|3] ""  MBMU,PC
 SG_ TMS_RunState_14 : 2|2@1+ (1,0) [0|3] ""  MBMU,PC
 SG_ TMS_CommuFault_14 : 4|1@1+ (1,0) [0|1] ""  MBMU,PC
 SG_ TMS_ModeConflict_14 : 5|1@1+ (1,0) [0|1] ""  MBMU,PC
 SG_ TMS_MakeBMSStop_14 : 6|1@1+ (1,0) [0|1] ""  MBMU,PC
 SG_ TMS_HVRealyState_14 : 7|1@1+ (1,0) [0|1] ""  MBMU,PC
 SG_ TMS_FaultCode_14 : 8|6@1+ (1,0) [0|63] ""  MBMU,PC
 SG_ TMS_FaultLevel_14 : 14|2@1+ (1,0) [0|3] ""  MBMU,PC
 SG_ B2T_TmptSetPoint_14 : 16|8@1+ (1,-50) [-50|210] "℃"  MBMU,PC
 SG_ TMS_OutWaterTemp_14 : 24|8@1+ (1,-50) [-50|210] "℃"  MBMU,PC
 SG_ TMS_BackWaterTemp_14 : 32|8@1+ (1,-50) [-50|210] "℃"  MBMU,PC
 SG_ TMS_EnvTemp_14 : 40|8@1+ (1,-50) [-50|210] "℃"  MBMU,PC
 SG_ TMS_RequestPower_14 : 48|8@1+ (0.1,0) [0|100] "Kw"  MBMU,PC
 SG_ STMS_ThrmStopReason_14 : 56|3@1+ (1,0) [0|3] ""  MBMU,PC

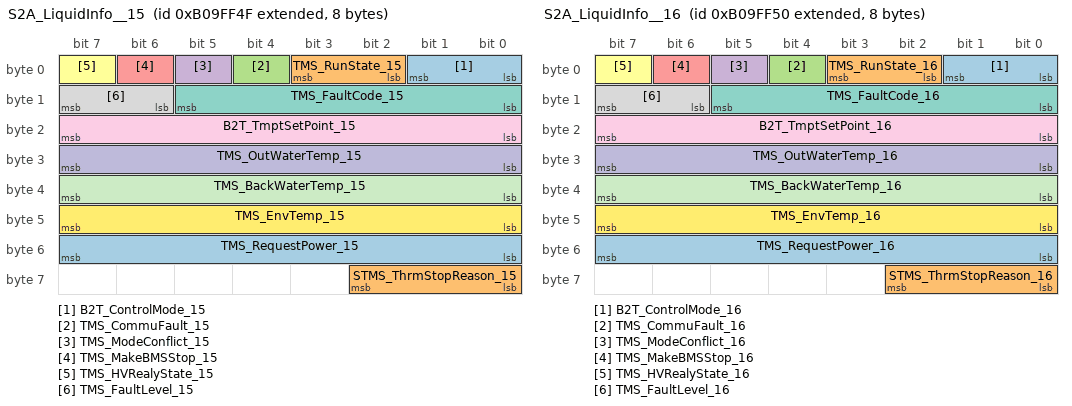
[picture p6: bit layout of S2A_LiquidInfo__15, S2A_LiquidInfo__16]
BO_ 2332688207 S2A_LiquidInfo__15: 8 SBMU
 SG_ B2T_ControlMode_15 : 0|2@1+ (1,0) [0|3] ""  MBMU,PC
 SG_ TMS_RunState_15 : 2|2@1+ (1,0) [0|3] ""  MBMU,PC
 SG_ TMS_CommuFault_15 : 4|1@1+ (1,0) [0|1] ""  MBMU,PC
 SG_ TMS_ModeConflict_15 : 5|1@1+ (1,0) [0|1] ""  MBMU,PC
 SG_ TMS_MakeBMSStop_15 : 6|1@1+ (1,0) [0|1] ""  MBMU,PC
 SG_ TMS_HVRealyState_15 : 7|1@1+ (1,0) [0|1] ""  MBMU,PC
 SG_ TMS_FaultCode_15 : 8|6@1+ (1,0) [0|63] ""  MBMU,PC
 SG_ TMS_FaultLevel_15 : 14|2@1+ (1,0) [0|3] ""  MBMU,PC
 SG_ B2T_TmptSetPoint_15 : 16|8@1+ (1,-50) [-50|210] "℃"  MBMU,PC
 SG_ TMS_OutWaterTemp_15 : 24|8@1+ (1,-50) [-50|210] "℃"  MBMU,PC
 SG_ TMS_BackWaterTemp_15 : 32|8@1+ (1,-50) [-50|210] "℃"  MBMU,PC
 SG_ TMS_EnvTemp_15 : 40|8@1+ (1,-50) [-50|210] "℃"  MBMU,PC
 SG_ TMS_RequestPower_15 : 48|8@1+ (0.1,0) [0|100] "Kw"  MBMU,PC
 SG_ STMS_ThrmStopReason_15 : 56|3@1+ (1,0) [0|3] ""  MBMU,PC

BO_ 2332688208 S2A_LiquidInfo__16: 8 SBMU
 SG_ B2T_ControlMode_16 : 0|2@1+ (1,0) [0|3] ""  MBMU,PC
 SG_ TMS_RunState_16 : 2|2@1+ (1,0) [0|3] ""  MBMU,PC
 SG_ TMS_CommuFault_16 : 4|1@1+ (1,0) [0|1] ""  MBMU,PC
 SG_ TMS_ModeConflict_16 : 5|1@1+ (1,0) [0|1] ""  MBMU,PC
 SG_ TMS_MakeBMSStop_16 : 6|1@1+ (1,0) [0|1] ""  MBMU,PC
 SG_ TMS_HVRealyState_16 : 7|1@1+ (1,0) [0|1] ""  MBMU,PC
 SG_ TMS_FaultCode_16 : 8|6@1+ (1,0) [0|63] ""  MBMU,PC
 SG_ TMS_FaultLevel_16 : 14|2@1+ (1,0) [0|3] ""  MBMU,PC
 SG_ B2T_TmptSetPoint_16 : 16|8@1+ (1,-50) [-50|210] "℃"  MBMU,PC
 SG_ TMS_OutWaterTemp_16 : 24|8@1+ (1,-50) [-50|210] "℃"  MBMU,PC
 SG_ TMS_BackWaterTemp_16 : 32|8@1+ (1,-50) [-50|210] "℃"  MBMU,PC
 SG_ TMS_EnvTemp_16 : 40|8@1+ (1,-50) [-50|210] "℃"  MBMU,PC
 SG_ TMS_RequestPower_16 : 48|8@1+ (0.1,0) [0|100] "Kw"  MBMU,PC
 SG_ STMS_ThrmStopReason_16 : 56|3@1+ (1,0) [0|3] ""  MBMU,PC

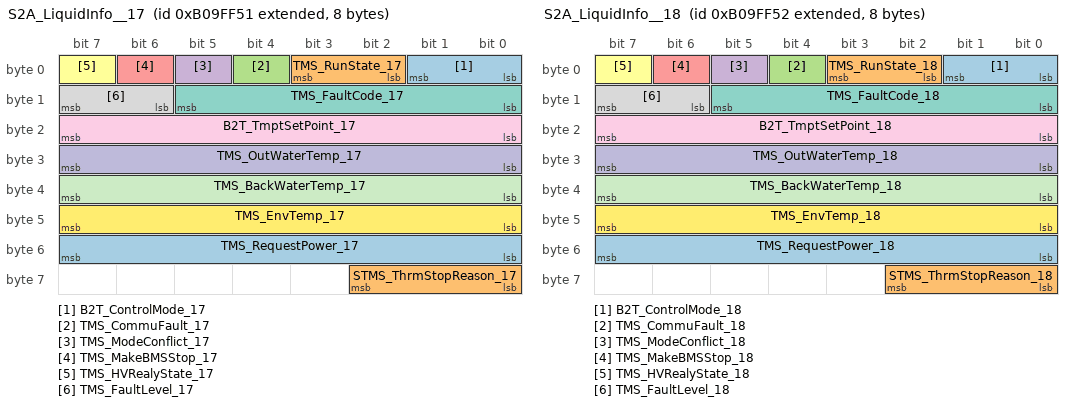
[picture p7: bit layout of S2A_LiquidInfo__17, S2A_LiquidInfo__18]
BO_ 2332688209 S2A_LiquidInfo__17: 8 SBMU
 SG_ B2T_ControlMode_17 : 0|2@1+ (1,0) [0|3] ""  MBMU,PC
 SG_ TMS_RunState_17 : 2|2@1+ (1,0) [0|3] ""  MBMU,PC
 SG_ TMS_CommuFault_17 : 4|1@1+ (1,0) [0|1] ""  MBMU,PC
 SG_ TMS_ModeConflict_17 : 5|1@1+ (1,0) [0|1] ""  MBMU,PC
 SG_ TMS_MakeBMSStop_17 : 6|1@1+ (1,0) [0|1] ""  MBMU,PC
 SG_ TMS_HVRealyState_17 : 7|1@1+ (1,0) [0|1] ""  MBMU,PC
 SG_ TMS_FaultCode_17 : 8|6@1+ (1,0) [0|63] ""  MBMU,PC
 SG_ TMS_FaultLevel_17 : 14|2@1+ (1,0) [0|3] ""  MBMU,PC
 SG_ B2T_TmptSetPoint_17 : 16|8@1+ (1,-50) [-50|210] "℃"  MBMU,PC
 SG_ TMS_OutWaterTemp_17 : 24|8@1+ (1,-50) [-50|210] "℃"  MBMU,PC
 SG_ TMS_BackWaterTemp_17 : 32|8@1+ (1,-50) [-50|210] "℃"  MBMU,PC
 SG_ TMS_EnvTemp_17 : 40|8@1+ (1,-50) [-50|210] "℃"  MBMU,PC
 SG_ TMS_RequestPower_17 : 48|8@1+ (0.1,0) [0|100] "Kw"  MBMU,PC
 SG_ STMS_ThrmStopReason_17 : 56|3@1+ (1,0) [0|3] ""  MBMU,PC

BO_ 2332688210 S2A_LiquidInfo__18: 8 SBMU
 SG_ B2T_ControlMode_18 : 0|2@1+ (1,0) [0|3] ""  MBMU,PC
 SG_ TMS_RunState_18 : 2|2@1+ (1,0) [0|3] ""  MBMU,PC
 SG_ TMS_CommuFault_18 : 4|1@1+ (1,0) [0|1] ""  MBMU,PC
 SG_ TMS_ModeConflict_18 : 5|1@1+ (1,0) [0|1] ""  MBMU,PC
 SG_ TMS_MakeBMSStop_18 : 6|1@1+ (1,0) [0|1] ""  MBMU,PC
 SG_ TMS_HVRealyState_18 : 7|1@1+ (1,0) [0|1] ""  MBMU,PC
 SG_ TMS_FaultCode_18 : 8|6@1+ (1,0) [0|63] ""  MBMU,PC
 SG_ TMS_FaultLevel_18 : 14|2@1+ (1,0) [0|3] ""  MBMU,PC
 SG_ B2T_TmptSetPoint_18 : 16|8@1+ (1,-50) [-50|210] "℃"  MBMU,PC
 SG_ TMS_OutWaterTemp_18 : 24|8@1+ (1,-50) [-50|210] "℃"  MBMU,PC
 SG_ TMS_BackWaterTemp_18 : 32|8@1+ (1,-50) [-50|210] "℃"  MBMU,PC
 SG_ TMS_EnvTemp_18 : 40|8@1+ (1,-50) [-50|210] "℃"  MBMU,PC
 SG_ TMS_RequestPower_18 : 48|8@1+ (0.1,0) [0|100] "Kw"  MBMU,PC
 SG_ STMS_ThrmStopReason_18 : 56|3@1+ (1,0) [0|3] ""  MBMU,PC

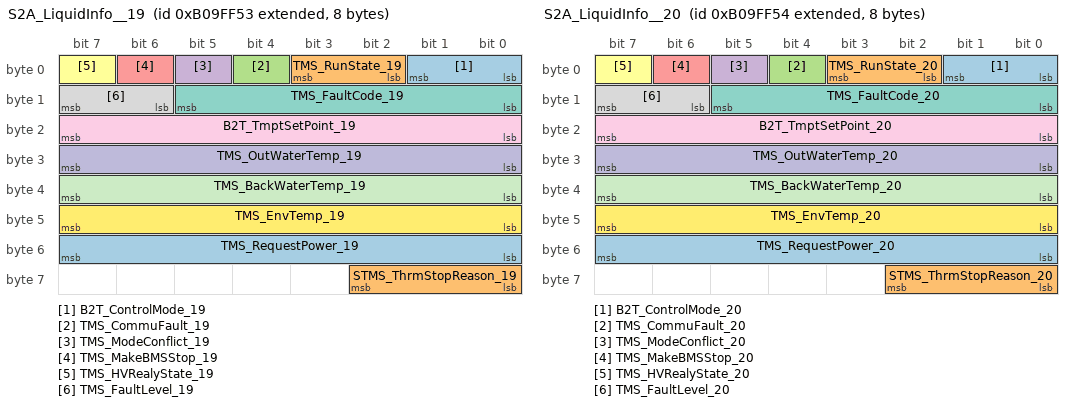
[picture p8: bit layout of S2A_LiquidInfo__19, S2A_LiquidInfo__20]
BO_ 2332688211 S2A_LiquidInfo__19: 8 SBMU
 SG_ B2T_ControlMode_19 : 0|2@1+ (1,0) [0|3] ""  MBMU,PC
 SG_ TMS_RunState_19 : 2|2@1+ (1,0) [0|3] ""  MBMU,PC
 SG_ TMS_CommuFault_19 : 4|1@1+ (1,0) [0|1] ""  MBMU,PC
 SG_ TMS_ModeConflict_19 : 5|1@1+ (1,0) [0|1] ""  MBMU,PC
 SG_ TMS_MakeBMSStop_19 : 6|1@1+ (1,0) [0|1] ""  MBMU,PC
 SG_ TMS_HVRealyState_19 : 7|1@1+ (1,0) [0|1] ""  MBMU,PC
 SG_ TMS_FaultCode_19 : 8|6@1+ (1,0) [0|63] ""  MBMU,PC
 SG_ TMS_FaultLevel_19 : 14|2@1+ (1,0) [0|3] ""  MBMU,PC
 SG_ B2T_TmptSetPoint_19 : 16|8@1+ (1,-50) [-50|210] "℃"  MBMU,PC
 SG_ TMS_OutWaterTemp_19 : 24|8@1+ (1,-50) [-50|210] "℃"  MBMU,PC
 SG_ TMS_BackWaterTemp_19 : 32|8@1+ (1,-50) [-50|210] "℃"  MBMU,PC
 SG_ TMS_EnvTemp_19 : 40|8@1+ (1,-50) [-50|210] "℃"  MBMU,PC
 SG_ TMS_RequestPower_19 : 48|8@1+ (0.1,0) [0|100] "Kw"  MBMU,PC
 SG_ STMS_ThrmStopReason_19 : 56|3@1+ (1,0) [0|3] ""  MBMU,PC

BO_ 2332688212 S2A_LiquidInfo__20: 8 SBMU
 SG_ B2T_ControlMode_20 : 0|2@1+ (1,0) [0|3] ""  MBMU,PC
 SG_ TMS_RunState_20 : 2|2@1+ (1,0) [0|3] ""  MBMU,PC
 SG_ TMS_CommuFault_20 : 4|1@1+ (1,0) [0|1] ""  MBMU,PC
 SG_ TMS_ModeConflict_20 : 5|1@1+ (1,0) [0|1] ""  MBMU,PC
 SG_ TMS_MakeBMSStop_20 : 6|1@1+ (1,0) [0|1] ""  MBMU,PC
 SG_ TMS_HVRealyState_20 : 7|1@1+ (1,0) [0|1] ""  MBMU,PC
 SG_ TMS_FaultCode_20 : 8|6@1+ (1,0) [0|63] ""  MBMU,PC
 SG_ TMS_FaultLevel_20 : 14|2@1+ (1,0) [0|3] ""  MBMU,PC
 SG_ B2T_TmptSetPoint_20 : 16|8@1+ (1,-50) [-50|210] "℃"  MBMU,PC
 SG_ TMS_OutWaterTemp_20 : 24|8@1+ (1,-50) [-50|210] "℃"  MBMU,PC
 SG_ TMS_BackWaterTemp_20 : 32|8@1+ (1,-50) [-50|210] "℃"  MBMU,PC
 SG_ TMS_EnvTemp_20 : 40|8@1+ (1,-50) [-50|210] "℃"  MBMU,PC
 SG_ TMS_RequestPower_20 : 48|8@1+ (0.1,0) [0|100] "Kw"  MBMU,PC
 SG_ STMS_ThrmStopReason_20 : 56|3@1+ (1,0) [0|3] ""  MBMU,PC

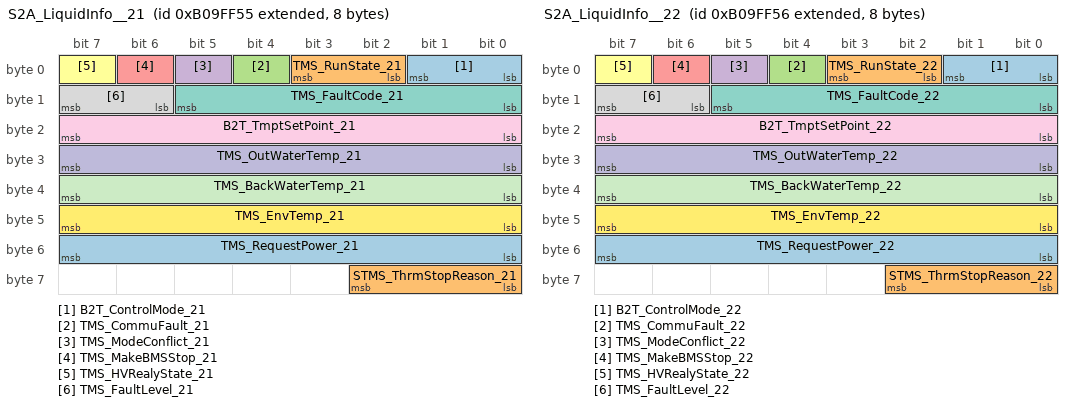
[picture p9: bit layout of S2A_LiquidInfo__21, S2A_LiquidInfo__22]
BO_ 2332688213 S2A_LiquidInfo__21: 8 SBMU
 SG_ B2T_ControlMode_21 : 0|2@1+ (1,0) [0|3] ""  MBMU,PC
 SG_ TMS_RunState_21 : 2|2@1+ (1,0) [0|3] ""  MBMU,PC
 SG_ TMS_CommuFault_21 : 4|1@1+ (1,0) [0|1] ""  MBMU,PC
 SG_ TMS_ModeConflict_21 : 5|1@1+ (1,0) [0|1] ""  MBMU,PC
 SG_ TMS_MakeBMSStop_21 : 6|1@1+ (1,0) [0|1] ""  MBMU,PC
 SG_ TMS_HVRealyState_21 : 7|1@1+ (1,0) [0|1] ""  MBMU,PC
 SG_ TMS_FaultCode_21 : 8|6@1+ (1,0) [0|63] ""  MBMU,PC
 SG_ TMS_FaultLevel_21 : 14|2@1+ (1,0) [0|3] ""  MBMU,PC
 SG_ B2T_TmptSetPoint_21 : 16|8@1+ (1,-50) [-50|210] "℃"  MBMU,PC
 SG_ TMS_OutWaterTemp_21 : 24|8@1+ (1,-50) [-50|210] "℃"  MBMU,PC
 SG_ TMS_BackWaterTemp_21 : 32|8@1+ (1,-50) [-50|210] "℃"  MBMU,PC
 SG_ TMS_EnvTemp_21 : 40|8@1+ (1,-50) [-50|210] "℃"  MBMU,PC
 SG_ TMS_RequestPower_21 : 48|8@1+ (0.1,0) [0|100] "Kw"  MBMU,PC
 SG_ STMS_ThrmStopReason_21 : 56|3@1+ (1,0) [0|3] ""  MBMU,PC

BO_ 2332688214 S2A_LiquidInfo__22: 8 SBMU
 SG_ B2T_ControlMode_22 : 0|2@1+ (1,0) [0|3] ""  MBMU,PC
 SG_ TMS_RunState_22 : 2|2@1+ (1,0) [0|3] ""  MBMU,PC
 SG_ TMS_CommuFault_22 : 4|1@1+ (1,0) [0|1] ""  MBMU,PC
 SG_ TMS_ModeConflict_22 : 5|1@1+ (1,0) [0|1] ""  MBMU,PC
 SG_ TMS_MakeBMSStop_22 : 6|1@1+ (1,0) [0|1] ""  MBMU,PC
 SG_ TMS_HVRealyState_22 : 7|1@1+ (1,0) [0|1] ""  MBMU,PC
 SG_ TMS_FaultCode_22 : 8|6@1+ (1,0) [0|63] ""  MBMU,PC
 SG_ TMS_FaultLevel_22 : 14|2@1+ (1,0) [0|3] ""  MBMU,PC
 SG_ B2T_TmptSetPoint_22 : 16|8@1+ (1,-50) [-50|210] "℃"  MBMU,PC
 SG_ TMS_OutWaterTemp_22 : 24|8@1+ (1,-50) [-50|210] "℃"  MBMU,PC
 SG_ TMS_BackWaterTemp_22 : 32|8@1+ (1,-50) [-50|210] "℃"  MBMU,PC
 SG_ TMS_EnvTemp_22 : 40|8@1+ (1,-50) [-50|210] "℃"  MBMU,PC
 SG_ TMS_RequestPower_22 : 48|8@1+ (0.1,0) [0|100] "Kw"  MBMU,PC
 SG_ STMS_ThrmStopReason_22 : 56|3@1+ (1,0) [0|3] ""  MBMU,PC

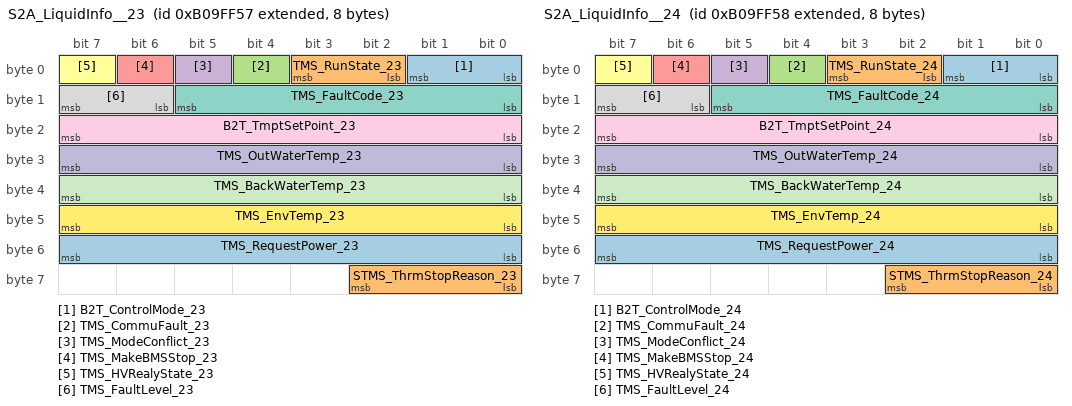
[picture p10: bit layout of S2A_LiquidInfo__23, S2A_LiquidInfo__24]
BO_ 2332688215 S2A_LiquidInfo__23: 8 SBMU
 SG_ B2T_ControlMode_23 : 0|2@1+ (1,0) [0|3] ""  MBMU,PC
 SG_ TMS_RunState_23 : 2|2@1+ (1,0) [0|3] ""  MBMU,PC
 SG_ TMS_CommuFault_23 : 4|1@1+ (1,0) [0|1] ""  MBMU,PC
 SG_ TMS_ModeConflict_23 : 5|1@1+ (1,0) [0|1] ""  MBMU,PC
 SG_ TMS_MakeBMSStop_23 : 6|1@1+ (1,0) [0|1] ""  MBMU,PC
 SG_ TMS_HVRealyState_23 : 7|1@1+ (1,0) [0|1] ""  MBMU,PC
 SG_ TMS_FaultCode_23 : 8|6@1+ (1,0) [0|63] ""  MBMU,PC
 SG_ TMS_FaultLevel_23 : 14|2@1+ (1,0) [0|3] ""  MBMU,PC
 SG_ B2T_TmptSetPoint_23 : 16|8@1+ (1,-50) [-50|210] "℃"  MBMU,PC
 SG_ TMS_OutWaterTemp_23 : 24|8@1+ (1,-50) [-50|210] "℃"  MBMU,PC
 SG_ TMS_BackWaterTemp_23 : 32|8@1+ (1,-50) [-50|210] "℃"  MBMU,PC
 SG_ TMS_EnvTemp_23 : 40|8@1+ (1,-50) [-50|210] "℃"  MBMU,PC
 SG_ TMS_RequestPower_23 : 48|8@1+ (0.1,0) [0|100] "Kw"  MBMU,PC
 SG_ STMS_ThrmStopReason_23 : 56|3@1+ (1,0) [0|3] ""  MBMU,PC

BO_ 2332688216 S2A_LiquidInfo__24: 8 SBMU
 SG_ B2T_ControlMode_24 : 0|2@1+ (1,0) [0|3] ""  MBMU,PC
 SG_ TMS_RunState_24 : 2|2@1+ (1,0) [0|3] ""  MBMU,PC
 SG_ TMS_CommuFault_24 : 4|1@1+ (1,0) [0|1] ""  MBMU,PC
 SG_ TMS_ModeConflict_24 : 5|1@1+ (1,0) [0|1] ""  MBMU,PC
 SG_ TMS_MakeBMSStop_24 : 6|1@1+ (1,0) [0|1] ""  MBMU,PC
 SG_ TMS_HVRealyState_24 : 7|1@1+ (1,0) [0|1] ""  MBMU,PC
 SG_ TMS_FaultCode_24 : 8|6@1+ (1,0) [0|63] ""  MBMU,PC
 SG_ TMS_FaultLevel_24 : 14|2@1+ (1,0) [0|3] ""  MBMU,PC
 SG_ B2T_TmptSetPoint_24 : 16|8@1+ (1,-50) [-50|210] "℃"  MBMU,PC
 SG_ TMS_OutWaterTemp_24 : 24|8@1+ (1,-50) [-50|210] "℃"  MBMU,PC
 SG_ TMS_BackWaterTemp_24 : 32|8@1+ (1,-50) [-50|210] "℃"  MBMU,PC
 SG_ TMS_EnvTemp_24 : 40|8@1+ (1,-50) [-50|210] "℃"  MBMU,PC
 SG_ TMS_RequestPower_24 : 48|8@1+ (0.1,0) [0|100] "Kw"  MBMU,PC
 SG_ STMS_ThrmStopReason_24 : 56|3@1+ (1,0) [0|3] ""  MBMU,PC

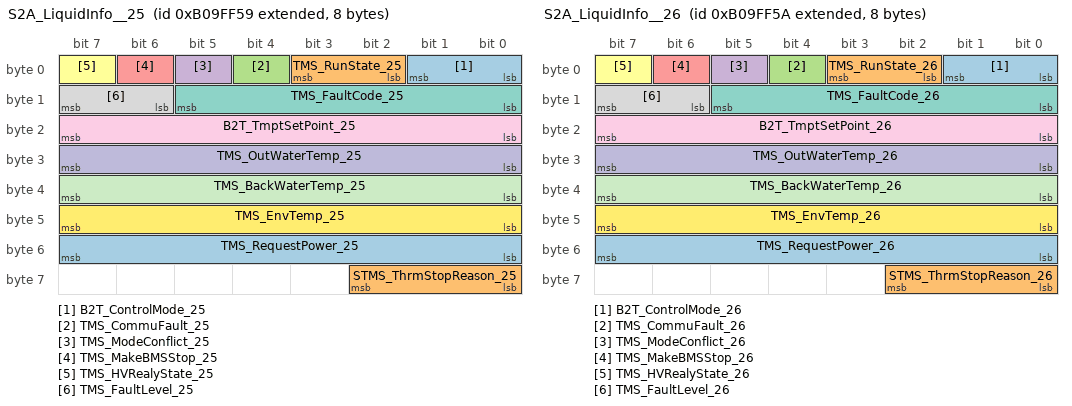
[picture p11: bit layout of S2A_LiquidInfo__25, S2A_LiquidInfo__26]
BO_ 2332688217 S2A_LiquidInfo__25: 8 SBMU
 SG_ B2T_ControlMode_25 : 0|2@1+ (1,0) [0|3] ""  MBMU,PC
 SG_ TMS_RunState_25 : 2|2@1+ (1,0) [0|3] ""  MBMU,PC
 SG_ TMS_CommuFault_25 : 4|1@1+ (1,0) [0|1] ""  MBMU,PC
 SG_ TMS_ModeConflict_25 : 5|1@1+ (1,0) [0|1] ""  MBMU,PC
 SG_ TMS_MakeBMSStop_25 : 6|1@1+ (1,0) [0|1] ""  MBMU,PC
 SG_ TMS_HVRealyState_25 : 7|1@1+ (1,0) [0|1] ""  MBMU,PC
 SG_ TMS_FaultCode_25 : 8|6@1+ (1,0) [0|63] ""  MBMU,PC
 SG_ TMS_FaultLevel_25 : 14|2@1+ (1,0) [0|3] ""  MBMU,PC
 SG_ B2T_TmptSetPoint_25 : 16|8@1+ (1,-50) [-50|210] "℃"  MBMU,PC
 SG_ TMS_OutWaterTemp_25 : 24|8@1+ (1,-50) [-50|210] "℃"  MBMU,PC
 SG_ TMS_BackWaterTemp_25 : 32|8@1+ (1,-50) [-50|210] "℃"  MBMU,PC
 SG_ TMS_EnvTemp_25 : 40|8@1+ (1,-50) [-50|210] "℃"  MBMU,PC
 SG_ TMS_RequestPower_25 : 48|8@1+ (0.1,0) [0|100] "Kw"  MBMU,PC
 SG_ STMS_ThrmStopReason_25 : 56|3@1+ (1,0) [0|3] ""  MBMU,PC

BO_ 2332688218 S2A_LiquidInfo__26: 8 SBMU
 SG_ B2T_ControlMode_26 : 0|2@1+ (1,0) [0|3] ""  MBMU,PC
 SG_ TMS_RunState_26 : 2|2@1+ (1,0) [0|3] ""  MBMU,PC
 SG_ TMS_CommuFault_26 : 4|1@1+ (1,0) [0|1] ""  MBMU,PC
 SG_ TMS_ModeConflict_26 : 5|1@1+ (1,0) [0|1] ""  MBMU,PC
 SG_ TMS_MakeBMSStop_26 : 6|1@1+ (1,0) [0|1] ""  MBMU,PC
 SG_ TMS_HVRealyState_26 : 7|1@1+ (1,0) [0|1] ""  MBMU,PC
 SG_ TMS_FaultCode_26 : 8|6@1+ (1,0) [0|63] ""  MBMU,PC
 SG_ TMS_FaultLevel_26 : 14|2@1+ (1,0) [0|3] ""  MBMU,PC
 SG_ B2T_TmptSetPoint_26 : 16|8@1+ (1,-50) [-50|210] "℃"  MBMU,PC
 SG_ TMS_OutWaterTemp_26 : 24|8@1+ (1,-50) [-50|210] "℃"  MBMU,PC
 SG_ TMS_BackWaterTemp_26 : 32|8@1+ (1,-50) [-50|210] "℃"  MBMU,PC
 SG_ TMS_EnvTemp_26 : 40|8@1+ (1,-50) [-50|210] "℃"  MBMU,PC
 SG_ TMS_RequestPower_26 : 48|8@1+ (0.1,0) [0|100] "Kw"  MBMU,PC
 SG_ STMS_ThrmStopReason_26 : 56|3@1+ (1,0) [0|3] ""  MBMU,PC

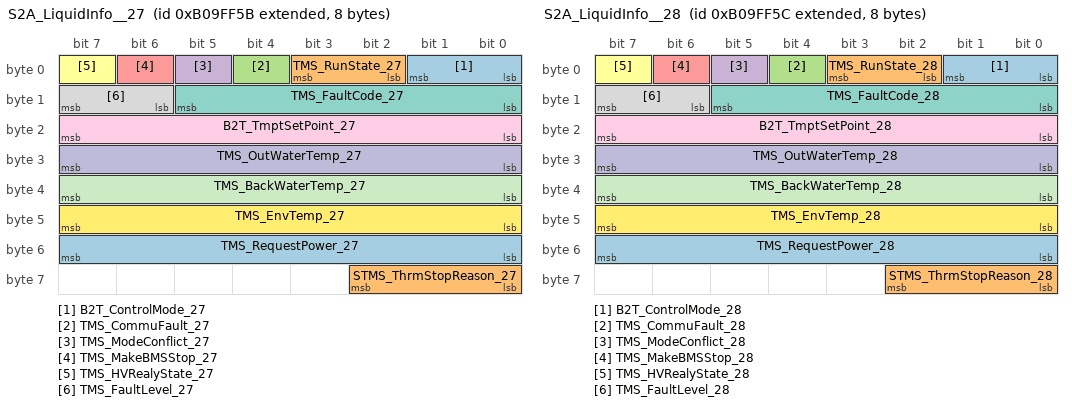
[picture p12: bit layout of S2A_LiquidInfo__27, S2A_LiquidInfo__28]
BO_ 2332688219 S2A_LiquidInfo__27: 8 SBMU
 SG_ B2T_ControlMode_27 : 0|2@1+ (1,0) [0|3] ""  MBMU,PC
 SG_ TMS_RunState_27 : 2|2@1+ (1,0) [0|3] ""  MBMU,PC
 SG_ TMS_CommuFault_27 : 4|1@1+ (1,0) [0|1] ""  MBMU,PC
 SG_ TMS_ModeConflict_27 : 5|1@1+ (1,0) [0|1] ""  MBMU,PC
 SG_ TMS_MakeBMSStop_27 : 6|1@1+ (1,0) [0|1] ""  MBMU,PC
 SG_ TMS_HVRealyState_27 : 7|1@1+ (1,0) [0|1] ""  MBMU,PC
 SG_ TMS_FaultCode_27 : 8|6@1+ (1,0) [0|63] ""  MBMU,PC
 SG_ TMS_FaultLevel_27 : 14|2@1+ (1,0) [0|3] ""  MBMU,PC
 SG_ B2T_TmptSetPoint_27 : 16|8@1+ (1,-50) [-50|210] "℃"  MBMU,PC
 SG_ TMS_OutWaterTemp_27 : 24|8@1+ (1,-50) [-50|210] "℃"  MBMU,PC
 SG_ TMS_BackWaterTemp_27 : 32|8@1+ (1,-50) [-50|210] "℃"  MBMU,PC
 SG_ TMS_EnvTemp_27 : 40|8@1+ (1,-50) [-50|210] "℃"  MBMU,PC
 SG_ TMS_RequestPower_27 : 48|8@1+ (0.1,0) [0|100] "Kw"  MBMU,PC
 SG_ STMS_ThrmStopReason_27 : 56|3@1+ (1,0) [0|3] ""  MBMU,PC

BO_ 2332688220 S2A_LiquidInfo__28: 8 SBMU
 SG_ B2T_ControlMode_28 : 0|2@1+ (1,0) [0|3] ""  MBMU,PC
 SG_ TMS_RunState_28 : 2|2@1+ (1,0) [0|3] ""  MBMU,PC
 SG_ TMS_CommuFault_28 : 4|1@1+ (1,0) [0|1] ""  MBMU,PC
 SG_ TMS_ModeConflict_28 : 5|1@1+ (1,0) [0|1] ""  MBMU,PC
 SG_ TMS_MakeBMSStop_28 : 6|1@1+ (1,0) [0|1] ""  MBMU,PC
 SG_ TMS_HVRealyState_28 : 7|1@1+ (1,0) [0|1] ""  MBMU,PC
 SG_ TMS_FaultCode_28 : 8|6@1+ (1,0) [0|63] ""  MBMU,PC
 SG_ TMS_FaultLevel_28 : 14|2@1+ (1,0) [0|3] ""  MBMU,PC
 SG_ B2T_TmptSetPoint_28 : 16|8@1+ (1,-50) [-50|210] "℃"  MBMU,PC
 SG_ TMS_OutWaterTemp_28 : 24|8@1+ (1,-50) [-50|210] "℃"  MBMU,PC
 SG_ TMS_BackWaterTemp_28 : 32|8@1+ (1,-50) [-50|210] "℃"  MBMU,PC
 SG_ TMS_EnvTemp_28 : 40|8@1+ (1,-50) [-50|210] "℃"  MBMU,PC
 SG_ TMS_RequestPower_28 : 48|8@1+ (0.1,0) [0|100] "Kw"  MBMU,PC
 SG_ STMS_ThrmStopReason_28 : 56|3@1+ (1,0) [0|3] ""  MBMU,PC

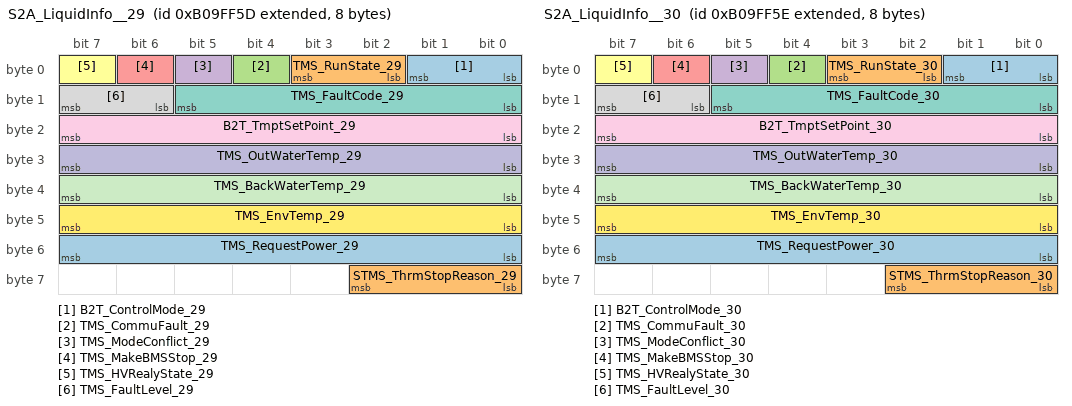
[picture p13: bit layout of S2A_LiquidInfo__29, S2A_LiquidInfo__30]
BO_ 2332688221 S2A_LiquidInfo__29: 8 SBMU
 SG_ B2T_ControlMode_29 : 0|2@1+ (1,0) [0|3] ""  MBMU,PC
 SG_ TMS_RunState_29 : 2|2@1+ (1,0) [0|3] ""  MBMU,PC
 SG_ TMS_CommuFault_29 : 4|1@1+ (1,0) [0|1] ""  MBMU,PC
 SG_ TMS_ModeConflict_29 : 5|1@1+ (1,0) [0|1] ""  MBMU,PC
 SG_ TMS_MakeBMSStop_29 : 6|1@1+ (1,0) [0|1] ""  MBMU,PC
 SG_ TMS_HVRealyState_29 : 7|1@1+ (1,0) [0|1] ""  MBMU,PC
 SG_ TMS_FaultCode_29 : 8|6@1+ (1,0) [0|63] ""  MBMU,PC
 SG_ TMS_FaultLevel_29 : 14|2@1+ (1,0) [0|3] ""  MBMU,PC
 SG_ B2T_TmptSetPoint_29 : 16|8@1+ (1,-50) [-50|210] "℃"  MBMU,PC
 SG_ TMS_OutWaterTemp_29 : 24|8@1+ (1,-50) [-50|210] "℃"  MBMU,PC
 SG_ TMS_BackWaterTemp_29 : 32|8@1+ (1,-50) [-50|210] "℃"  MBMU,PC
 SG_ TMS_EnvTemp_29 : 40|8@1+ (1,-50) [-50|210] "℃"  MBMU,PC
 SG_ TMS_RequestPower_29 : 48|8@1+ (0.1,0) [0|100] "Kw"  MBMU,PC
 SG_ STMS_ThrmStopReason_29 : 56|3@1+ (1,0) [0|3] ""  MBMU,PC

BO_ 2332688222 S2A_LiquidInfo__30: 8 SBMU
 SG_ B2T_ControlMode_30 : 0|2@1+ (1,0) [0|3] ""  MBMU,PC
 SG_ TMS_RunState_30 : 2|2@1+ (1,0) [0|3] ""  MBMU,PC
 SG_ TMS_CommuFault_30 : 4|1@1+ (1,0) [0|1] ""  MBMU,PC
 SG_ TMS_ModeConflict_30 : 5|1@1+ (1,0) [0|1] ""  MBMU,PC
 SG_ TMS_MakeBMSStop_30 : 6|1@1+ (1,0) [0|1] ""  MBMU,PC
 SG_ TMS_HVRealyState_30 : 7|1@1+ (1,0) [0|1] ""  MBMU,PC
 SG_ TMS_FaultCode_30 : 8|6@1+ (1,0) [0|63] ""  MBMU,PC
 SG_ TMS_FaultLevel_30 : 14|2@1+ (1,0) [0|3] ""  MBMU,PC
 SG_ B2T_TmptSetPoint_30 : 16|8@1+ (1,-50) [-50|210] "℃"  MBMU,PC
 SG_ TMS_OutWaterTemp_30 : 24|8@1+ (1,-50) [-50|210] "℃"  MBMU,PC
 SG_ TMS_BackWaterTemp_30 : 32|8@1+ (1,-50) [-50|210] "℃"  MBMU,PC
 SG_ TMS_EnvTemp_30 : 40|8@1+ (1,-50) [-50|210] "℃"  MBMU,PC
 SG_ TMS_RequestPower_30 : 48|8@1+ (0.1,0) [0|100] "Kw"  MBMU,PC
 SG_ STMS_ThrmStopReason_30 : 56|3@1+ (1,0) [0|3] ""  MBMU,PC

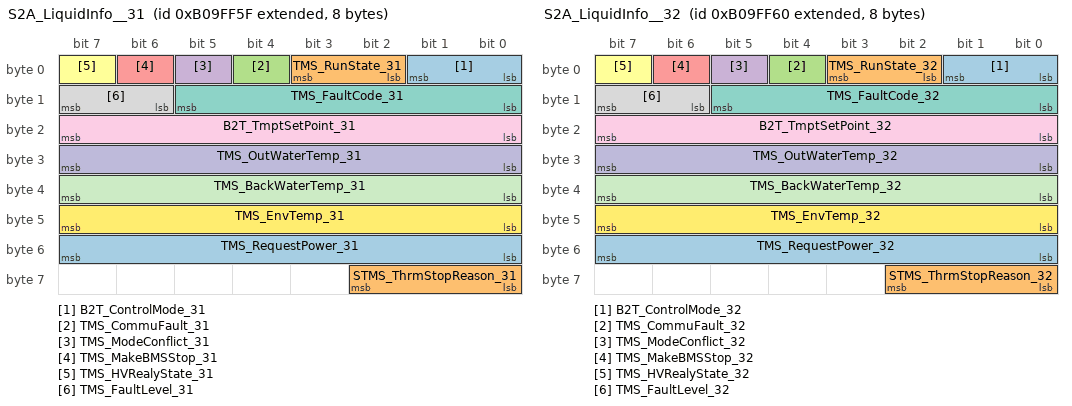
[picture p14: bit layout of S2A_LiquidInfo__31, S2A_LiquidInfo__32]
BO_ 2332688223 S2A_LiquidInfo__31: 8 SBMU
 SG_ B2T_ControlMode_31 : 0|2@1+ (1,0) [0|3] ""  MBMU,PC
 SG_ TMS_RunState_31 : 2|2@1+ (1,0) [0|3] ""  MBMU,PC
 SG_ TMS_CommuFault_31 : 4|1@1+ (1,0) [0|1] ""  MBMU,PC
 SG_ TMS_ModeConflict_31 : 5|1@1+ (1,0) [0|1] ""  MBMU,PC
 SG_ TMS_MakeBMSStop_31 : 6|1@1+ (1,0) [0|1] ""  MBMU,PC
 SG_ TMS_HVRealyState_31 : 7|1@1+ (1,0) [0|1] ""  MBMU,PC
 SG_ TMS_FaultCode_31 : 8|6@1+ (1,0) [0|63] ""  MBMU,PC
 SG_ TMS_FaultLevel_31 : 14|2@1+ (1,0) [0|3] ""  MBMU,PC
 SG_ B2T_TmptSetPoint_31 : 16|8@1+ (1,-50) [-50|210] "℃"  MBMU,PC
 SG_ TMS_OutWaterTemp_31 : 24|8@1+ (1,-50) [-50|210] "℃"  MBMU,PC
 SG_ TMS_BackWaterTemp_31 : 32|8@1+ (1,-50) [-50|210] "℃"  MBMU,PC
 SG_ TMS_EnvTemp_31 : 40|8@1+ (1,-50) [-50|210] "℃"  MBMU,PC
 SG_ TMS_RequestPower_31 : 48|8@1+ (0.1,0) [0|100] "Kw"  MBMU,PC
 SG_ STMS_ThrmStopReason_31 : 56|3@1+ (1,0) [0|3] ""  MBMU,PC

BO_ 2332688224 S2A_LiquidInfo__32: 8 SBMU
 SG_ B2T_ControlMode_32 : 0|2@1+ (1,0) [0|3] ""  MBMU,PC
 SG_ TMS_RunState_32 : 2|2@1+ (1,0) [0|3] ""  MBMU,PC
 SG_ TMS_CommuFault_32 : 4|1@1+ (1,0) [0|1] ""  MBMU,PC
 SG_ TMS_ModeConflict_32 : 5|1@1+ (1,0) [0|1] ""  MBMU,PC
 SG_ TMS_MakeBMSStop_32 : 6|1@1+ (1,0) [0|1] ""  MBMU,PC
 SG_ TMS_HVRealyState_32 : 7|1@1+ (1,0) [0|1] ""  MBMU,PC
 SG_ TMS_FaultCode_32 : 8|6@1+ (1,0) [0|63] ""  MBMU,PC
 SG_ TMS_FaultLevel_32 : 14|2@1+ (1,0) [0|3] ""  MBMU,PC
 SG_ B2T_TmptSetPoint_32 : 16|8@1+ (1,-50) [-50|210] "℃"  MBMU,PC
 SG_ TMS_OutWaterTemp_32 : 24|8@1+ (1,-50) [-50|210] "℃"  MBMU,PC
 SG_ TMS_BackWaterTemp_32 : 32|8@1+ (1,-50) [-50|210] "℃"  MBMU,PC
 SG_ TMS_EnvTemp_32 : 40|8@1+ (1,-50) [-50|210] "℃"  MBMU,PC
 SG_ TMS_RequestPower_32 : 48|8@1+ (0.1,0) [0|100] "Kw"  MBMU,PC
 SG_ STMS_ThrmStopReason_32 : 56|3@1+ (1,0) [0|3] ""  MBMU,PC

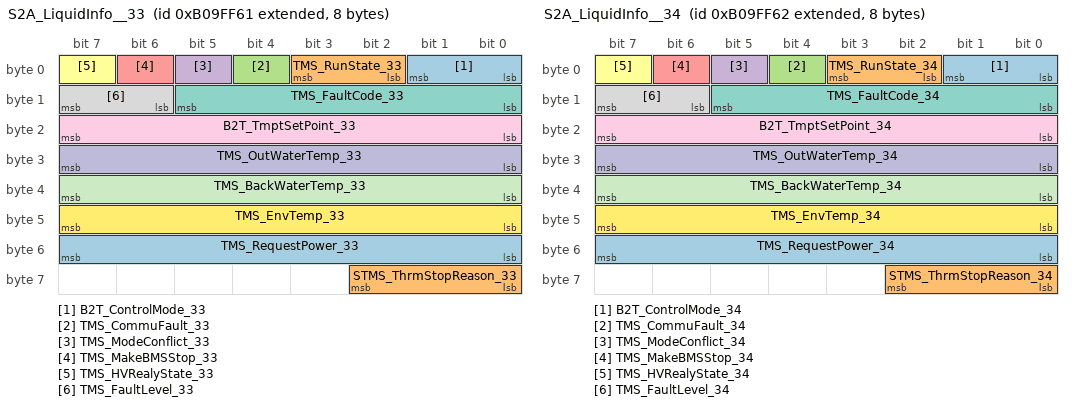
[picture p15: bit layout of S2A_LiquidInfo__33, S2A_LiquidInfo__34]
BO_ 2332688225 S2A_LiquidInfo__33: 8 SBMU
 SG_ B2T_ControlMode_33 : 0|2@1+ (1,0) [0|3] ""  MBMU,PC
 SG_ TMS_RunState_33 : 2|2@1+ (1,0) [0|3] ""  MBMU,PC
 SG_ TMS_CommuFault_33 : 4|1@1+ (1,0) [0|1] ""  MBMU,PC
 SG_ TMS_ModeConflict_33 : 5|1@1+ (1,0) [0|1] ""  MBMU,PC
 SG_ TMS_MakeBMSStop_33 : 6|1@1+ (1,0) [0|1] ""  MBMU,PC
 SG_ TMS_HVRealyState_33 : 7|1@1+ (1,0) [0|1] ""  MBMU,PC
 SG_ TMS_FaultCode_33 : 8|6@1+ (1,0) [0|63] ""  MBMU,PC
 SG_ TMS_FaultLevel_33 : 14|2@1+ (1,0) [0|3] ""  MBMU,PC
 SG_ B2T_TmptSetPoint_33 : 16|8@1+ (1,-50) [-50|210] "℃"  MBMU,PC
 SG_ TMS_OutWaterTemp_33 : 24|8@1+ (1,-50) [-50|210] "℃"  MBMU,PC
 SG_ TMS_BackWaterTemp_33 : 32|8@1+ (1,-50) [-50|210] "℃"  MBMU,PC
 SG_ TMS_EnvTemp_33 : 40|8@1+ (1,-50) [-50|210] "℃"  MBMU,PC
 SG_ TMS_RequestPower_33 : 48|8@1+ (0.1,0) [0|100] "Kw"  MBMU,PC
 SG_ STMS_ThrmStopReason_33 : 56|3@1+ (1,0) [0|3] ""  MBMU,PC

BO_ 2332688226 S2A_LiquidInfo__34: 8 SBMU
 SG_ B2T_ControlMode_34 : 0|2@1+ (1,0) [0|3] ""  MBMU,PC
 SG_ TMS_RunState_34 : 2|2@1+ (1,0) [0|3] ""  MBMU,PC
 SG_ TMS_CommuFault_34 : 4|1@1+ (1,0) [0|1] ""  MBMU,PC
 SG_ TMS_ModeConflict_34 : 5|1@1+ (1,0) [0|1] ""  MBMU,PC
 SG_ TMS_MakeBMSStop_34 : 6|1@1+ (1,0) [0|1] ""  MBMU,PC
 SG_ TMS_HVRealyState_34 : 7|1@1+ (1,0) [0|1] ""  MBMU,PC
 SG_ TMS_FaultCode_34 : 8|6@1+ (1,0) [0|63] ""  MBMU,PC
 SG_ TMS_FaultLevel_34 : 14|2@1+ (1,0) [0|3] ""  MBMU,PC
 SG_ B2T_TmptSetPoint_34 : 16|8@1+ (1,-50) [-50|210] "℃"  MBMU,PC
 SG_ TMS_OutWaterTemp_34 : 24|8@1+ (1,-50) [-50|210] "℃"  MBMU,PC
 SG_ TMS_BackWaterTemp_34 : 32|8@1+ (1,-50) [-50|210] "℃"  MBMU,PC
 SG_ TMS_EnvTemp_34 : 40|8@1+ (1,-50) [-50|210] "℃"  MBMU,PC
 SG_ TMS_RequestPower_34 : 48|8@1+ (0.1,0) [0|100] "Kw"  MBMU,PC
 SG_ STMS_ThrmStopReason_34 : 56|3@1+ (1,0) [0|3] ""  MBMU,PC

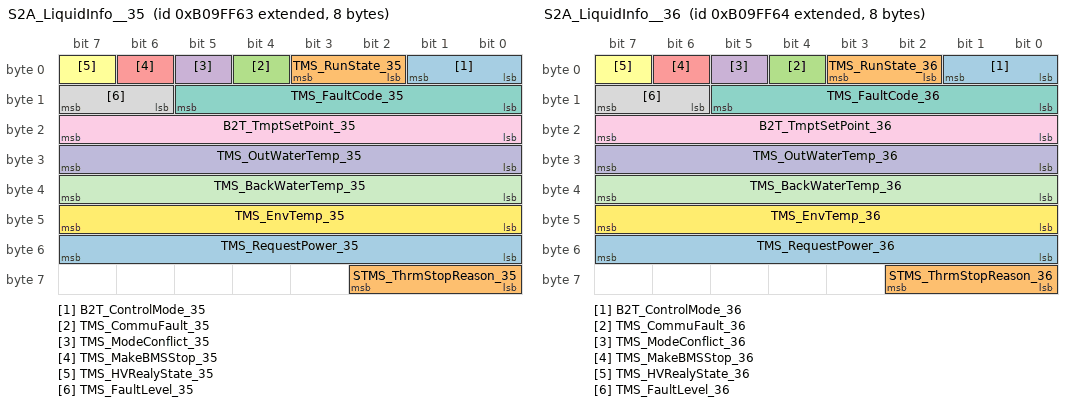
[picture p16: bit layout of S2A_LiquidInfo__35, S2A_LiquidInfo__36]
BO_ 2332688227 S2A_LiquidInfo__35: 8 SBMU
 SG_ B2T_ControlMode_35 : 0|2@1+ (1,0) [0|3] ""  MBMU,PC
 SG_ TMS_RunState_35 : 2|2@1+ (1,0) [0|3] ""  MBMU,PC
 SG_ TMS_CommuFault_35 : 4|1@1+ (1,0) [0|1] ""  MBMU,PC
 SG_ TMS_ModeConflict_35 : 5|1@1+ (1,0) [0|1] ""  MBMU,PC
 SG_ TMS_MakeBMSStop_35 : 6|1@1+ (1,0) [0|1] ""  MBMU,PC
 SG_ TMS_HVRealyState_35 : 7|1@1+ (1,0) [0|1] ""  MBMU,PC
 SG_ TMS_FaultCode_35 : 8|6@1+ (1,0) [0|63] ""  MBMU,PC
 SG_ TMS_FaultLevel_35 : 14|2@1+ (1,0) [0|3] ""  MBMU,PC
 SG_ B2T_TmptSetPoint_35 : 16|8@1+ (1,-50) [-50|210] "℃"  MBMU,PC
 SG_ TMS_OutWaterTemp_35 : 24|8@1+ (1,-50) [-50|210] "℃"  MBMU,PC
 SG_ TMS_BackWaterTemp_35 : 32|8@1+ (1,-50) [-50|210] "℃"  MBMU,PC
 SG_ TMS_EnvTemp_35 : 40|8@1+ (1,-50) [-50|210] "℃"  MBMU,PC
 SG_ TMS_RequestPower_35 : 48|8@1+ (0.1,0) [0|100] "Kw"  MBMU,PC
 SG_ STMS_ThrmStopReason_35 : 56|3@1+ (1,0) [0|3] ""  MBMU,PC

BO_ 2332688228 S2A_LiquidInfo__36: 8 SBMU
 SG_ B2T_ControlMode_36 : 0|2@1+ (1,0) [0|3] ""  MBMU,PC
 SG_ TMS_RunState_36 : 2|2@1+ (1,0) [0|3] ""  MBMU,PC
 SG_ TMS_CommuFault_36 : 4|1@1+ (1,0) [0|1] ""  MBMU,PC
 SG_ TMS_ModeConflict_36 : 5|1@1+ (1,0) [0|1] ""  MBMU,PC
 SG_ TMS_MakeBMSStop_36 : 6|1@1+ (1,0) [0|1] ""  MBMU,PC
 SG_ TMS_HVRealyState_36 : 7|1@1+ (1,0) [0|1] ""  MBMU,PC
 SG_ TMS_FaultCode_36 : 8|6@1+ (1,0) [0|63] ""  MBMU,PC
 SG_ TMS_FaultLevel_36 : 14|2@1+ (1,0) [0|3] ""  MBMU,PC
 SG_ B2T_TmptSetPoint_36 : 16|8@1+ (1,-50) [-50|210] "℃"  MBMU,PC
 SG_ TMS_OutWaterTemp_36 : 24|8@1+ (1,-50) [-50|210] "℃"  MBMU,PC
 SG_ TMS_BackWaterTemp_36 : 32|8@1+ (1,-50) [-50|210] "℃"  MBMU,PC
 SG_ TMS_EnvTemp_36 : 40|8@1+ (1,-50) [-50|210] "℃"  MBMU,PC
 SG_ TMS_RequestPower_36 : 48|8@1+ (0.1,0) [0|100] "Kw"  MBMU,PC
 SG_ STMS_ThrmStopReason_36 : 56|3@1+ (1,0) [0|3] ""  MBMU,PC

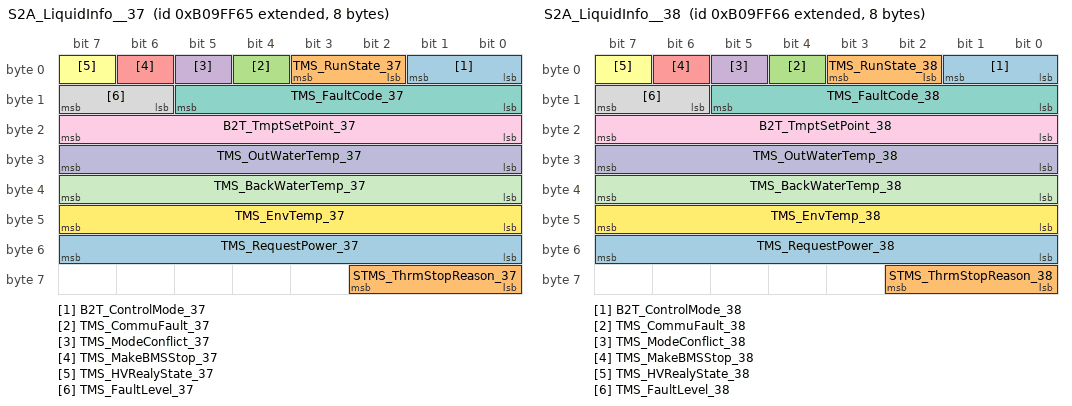
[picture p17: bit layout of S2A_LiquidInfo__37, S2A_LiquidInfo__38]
BO_ 2332688229 S2A_LiquidInfo__37: 8 SBMU
 SG_ B2T_ControlMode_37 : 0|2@1+ (1,0) [0|3] ""  MBMU,PC
 SG_ TMS_RunState_37 : 2|2@1+ (1,0) [0|3] ""  MBMU,PC
 SG_ TMS_CommuFault_37 : 4|1@1+ (1,0) [0|1] ""  MBMU,PC
 SG_ TMS_ModeConflict_37 : 5|1@1+ (1,0) [0|1] ""  MBMU,PC
 SG_ TMS_MakeBMSStop_37 : 6|1@1+ (1,0) [0|1] ""  MBMU,PC
 SG_ TMS_HVRealyState_37 : 7|1@1+ (1,0) [0|1] ""  MBMU,PC
 SG_ TMS_FaultCode_37 : 8|6@1+ (1,0) [0|63] ""  MBMU,PC
 SG_ TMS_FaultLevel_37 : 14|2@1+ (1,0) [0|3] ""  MBMU,PC
 SG_ B2T_TmptSetPoint_37 : 16|8@1+ (1,-50) [-50|210] "℃"  MBMU,PC
 SG_ TMS_OutWaterTemp_37 : 24|8@1+ (1,-50) [-50|210] "℃"  MBMU,PC
 SG_ TMS_BackWaterTemp_37 : 32|8@1+ (1,-50) [-50|210] "℃"  MBMU,PC
 SG_ TMS_EnvTemp_37 : 40|8@1+ (1,-50) [-50|210] "℃"  MBMU,PC
 SG_ TMS_RequestPower_37 : 48|8@1+ (0.1,0) [0|100] "Kw"  MBMU,PC
 SG_ STMS_ThrmStopReason_37 : 56|3@1+ (1,0) [0|3] ""  MBMU,PC

BO_ 2332688230 S2A_LiquidInfo__38: 8 SBMU
 SG_ B2T_ControlMode_38 : 0|2@1+ (1,0) [0|3] ""  MBMU,PC
 SG_ TMS_RunState_38 : 2|2@1+ (1,0) [0|3] ""  MBMU,PC
 SG_ TMS_CommuFault_38 : 4|1@1+ (1,0) [0|1] ""  MBMU,PC
 SG_ TMS_ModeConflict_38 : 5|1@1+ (1,0) [0|1] ""  MBMU,PC
 SG_ TMS_MakeBMSStop_38 : 6|1@1+ (1,0) [0|1] ""  MBMU,PC
 SG_ TMS_HVRealyState_38 : 7|1@1+ (1,0) [0|1] ""  MBMU,PC
 SG_ TMS_FaultCode_38 : 8|6@1+ (1,0) [0|63] ""  MBMU,PC
 SG_ TMS_FaultLevel_38 : 14|2@1+ (1,0) [0|3] ""  MBMU,PC
 SG_ B2T_TmptSetPoint_38 : 16|8@1+ (1,-50) [-50|210] "℃"  MBMU,PC
 SG_ TMS_OutWaterTemp_38 : 24|8@1+ (1,-50) [-50|210] "℃"  MBMU,PC
 SG_ TMS_BackWaterTemp_38 : 32|8@1+ (1,-50) [-50|210] "℃"  MBMU,PC
 SG_ TMS_EnvTemp_38 : 40|8@1+ (1,-50) [-50|210] "℃"  MBMU,PC
 SG_ TMS_RequestPower_38 : 48|8@1+ (0.1,0) [0|100] "Kw"  MBMU,PC
 SG_ STMS_ThrmStopReason_38 : 56|3@1+ (1,0) [0|3] ""  MBMU,PC

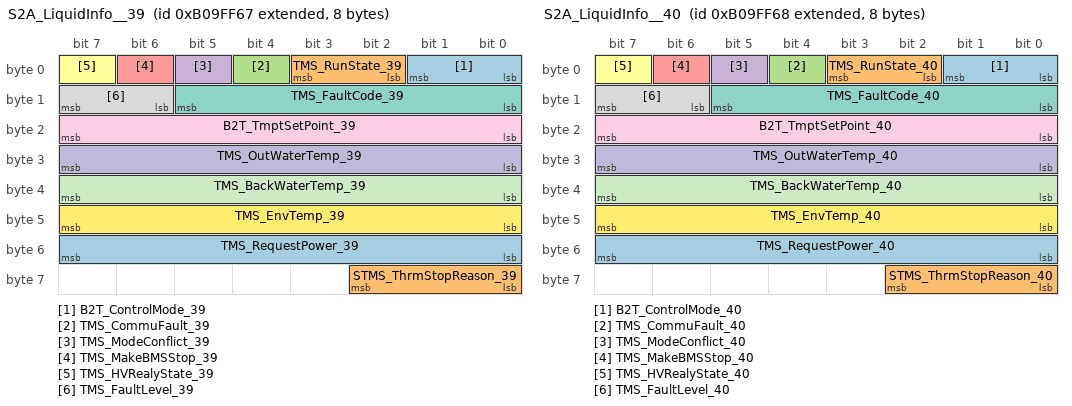
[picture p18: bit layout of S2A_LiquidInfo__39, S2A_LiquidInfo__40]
BO_ 2332688231 S2A_LiquidInfo__39: 8 SBMU
 SG_ B2T_ControlMode_39 : 0|2@1+ (1,0) [0|3] ""  MBMU,PC
 SG_ TMS_RunState_39 : 2|2@1+ (1,0) [0|3] ""  MBMU,PC
 SG_ TMS_CommuFault_39 : 4|1@1+ (1,0) [0|1] ""  MBMU,PC
 SG_ TMS_ModeConflict_39 : 5|1@1+ (1,0) [0|1] ""  MBMU,PC
 SG_ TMS_MakeBMSStop_39 : 6|1@1+ (1,0) [0|1] ""  MBMU,PC
 SG_ TMS_HVRealyState_39 : 7|1@1+ (1,0) [0|1] ""  MBMU,PC
 SG_ TMS_FaultCode_39 : 8|6@1+ (1,0) [0|63] ""  MBMU,PC
 SG_ TMS_FaultLevel_39 : 14|2@1+ (1,0) [0|3] ""  MBMU,PC
 SG_ B2T_TmptSetPoint_39 : 16|8@1+ (1,-50) [-50|210] "℃"  MBMU,PC
 SG_ TMS_OutWaterTemp_39 : 24|8@1+ (1,-50) [-50|210] "℃"  MBMU,PC
 SG_ TMS_BackWaterTemp_39 : 32|8@1+ (1,-50) [-50|210] "℃"  MBMU,PC
 SG_ TMS_EnvTemp_39 : 40|8@1+ (1,-50) [-50|210] "℃"  MBMU,PC
 SG_ TMS_RequestPower_39 : 48|8@1+ (0.1,0) [0|100] "Kw"  MBMU,PC
 SG_ STMS_ThrmStopReason_39 : 56|3@1+ (1,0) [0|3] ""  MBMU,PC

BO_ 2332688232 S2A_LiquidInfo__40: 8 SBMU
 SG_ B2T_ControlMode_40 : 0|2@1+ (1,0) [0|3] ""  MBMU,PC
 SG_ TMS_RunState_40 : 2|2@1+ (1,0) [0|3] ""  MBMU,PC
 SG_ TMS_CommuFault_40 : 4|1@1+ (1,0) [0|1] ""  MBMU,PC
 SG_ TMS_ModeConflict_40 : 5|1@1+ (1,0) [0|1] ""  MBMU,PC
 SG_ TMS_MakeBMSStop_40 : 6|1@1+ (1,0) [0|1] ""  MBMU,PC
 SG_ TMS_HVRealyState_40 : 7|1@1+ (1,0) [0|1] ""  MBMU,PC
 SG_ TMS_FaultCode_40 : 8|6@1+ (1,0) [0|63] ""  MBMU,PC
 SG_ TMS_FaultLevel_40 : 14|2@1+ (1,0) [0|3] ""  MBMU,PC
 SG_ B2T_TmptSetPoint_40 : 16|8@1+ (1,-50) [-50|210] "℃"  MBMU,PC
 SG_ TMS_OutWaterTemp_40 : 24|8@1+ (1,-50) [-50|210] "℃"  MBMU,PC
 SG_ TMS_BackWaterTemp_40 : 32|8@1+ (1,-50) [-50|210] "℃"  MBMU,PC
 SG_ TMS_EnvTemp_40 : 40|8@1+ (1,-50) [-50|210] "℃"  MBMU,PC
 SG_ TMS_RequestPower_40 : 48|8@1+ (0.1,0) [0|100] "Kw"  MBMU,PC
 SG_ STMS_ThrmStopReason_40 : 56|3@1+ (1,0) [0|3] ""  MBMU,PC

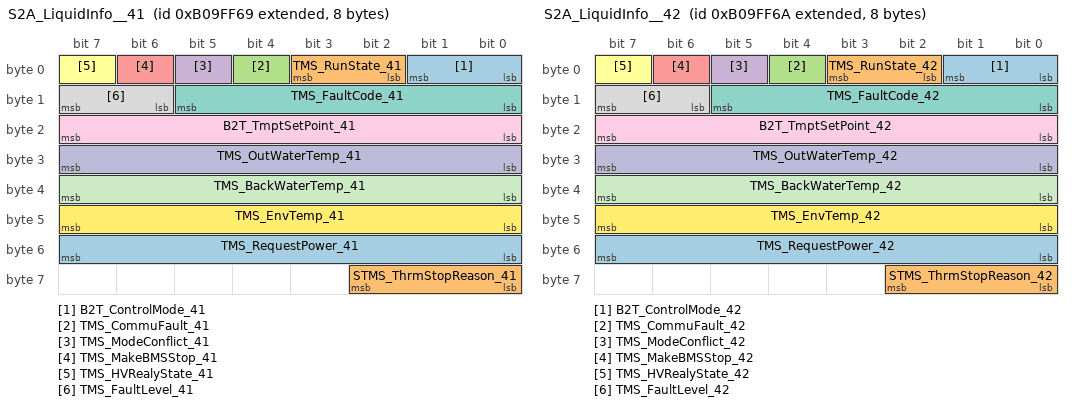
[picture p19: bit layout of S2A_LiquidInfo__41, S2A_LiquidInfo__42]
BO_ 2332688233 S2A_LiquidInfo__41: 8 SBMU
 SG_ B2T_ControlMode_41 : 0|2@1+ (1,0) [0|3] ""  MBMU,PC
 SG_ TMS_RunState_41 : 2|2@1+ (1,0) [0|3] ""  MBMU,PC
 SG_ TMS_CommuFault_41 : 4|1@1+ (1,0) [0|1] ""  MBMU,PC
 SG_ TMS_ModeConflict_41 : 5|1@1+ (1,0) [0|1] ""  MBMU,PC
 SG_ TMS_MakeBMSStop_41 : 6|1@1+ (1,0) [0|1] ""  MBMU,PC
 SG_ TMS_HVRealyState_41 : 7|1@1+ (1,0) [0|1] ""  MBMU,PC
 SG_ TMS_FaultCode_41 : 8|6@1+ (1,0) [0|63] ""  MBMU,PC
 SG_ TMS_FaultLevel_41 : 14|2@1+ (1,0) [0|3] ""  MBMU,PC
 SG_ B2T_TmptSetPoint_41 : 16|8@1+ (1,-50) [-50|210] "℃"  MBMU,PC
 SG_ TMS_OutWaterTemp_41 : 24|8@1+ (1,-50) [-50|210] "℃"  MBMU,PC
 SG_ TMS_BackWaterTemp_41 : 32|8@1+ (1,-50) [-50|210] "℃"  MBMU,PC
 SG_ TMS_EnvTemp_41 : 40|8@1+ (1,-50) [-50|210] "℃"  MBMU,PC
 SG_ TMS_RequestPower_41 : 48|8@1+ (0.1,0) [0|100] "Kw"  MBMU,PC
 SG_ STMS_ThrmStopReason_41 : 56|3@1+ (1,0) [0|3] ""  MBMU,PC

BO_ 2332688234 S2A_LiquidInfo__42: 8 SBMU
 SG_ B2T_ControlMode_42 : 0|2@1+ (1,0) [0|3] ""  MBMU,PC
 SG_ TMS_RunState_42 : 2|2@1+ (1,0) [0|3] ""  MBMU,PC
 SG_ TMS_CommuFault_42 : 4|1@1+ (1,0) [0|1] ""  MBMU,PC
 SG_ TMS_ModeConflict_42 : 5|1@1+ (1,0) [0|1] ""  MBMU,PC
 SG_ TMS_MakeBMSStop_42 : 6|1@1+ (1,0) [0|1] ""  MBMU,PC
 SG_ TMS_HVRealyState_42 : 7|1@1+ (1,0) [0|1] ""  MBMU,PC
 SG_ TMS_FaultCode_42 : 8|6@1+ (1,0) [0|63] ""  MBMU,PC
 SG_ TMS_FaultLevel_42 : 14|2@1+ (1,0) [0|3] ""  MBMU,PC
 SG_ B2T_TmptSetPoint_42 : 16|8@1+ (1,-50) [-50|210] "℃"  MBMU,PC
 SG_ TMS_OutWaterTemp_42 : 24|8@1+ (1,-50) [-50|210] "℃"  MBMU,PC
 SG_ TMS_BackWaterTemp_42 : 32|8@1+ (1,-50) [-50|210] "℃"  MBMU,PC
 SG_ TMS_EnvTemp_42 : 40|8@1+ (1,-50) [-50|210] "℃"  MBMU,PC
 SG_ TMS_RequestPower_42 : 48|8@1+ (0.1,0) [0|100] "Kw"  MBMU,PC
 SG_ STMS_ThrmStopReason_42 : 56|3@1+ (1,0) [0|3] ""  MBMU,PC

BO_ 2332688235 S2A_LiquidInfo__43: 8 SBMU
 SG_ B2T_ControlMode_43 : 0|2@1+ (1,0) [0|3] ""  MBMU,PC
 SG_ TMS_RunState_43 : 2|2@1+ (1,0) [0|3] ""  MBMU,PC
 SG_ TMS_CommuFault_43 : 4|1@1+ (1,0) [0|1] ""  MBMU,PC
 SG_ TMS_ModeConflict_43 : 5|1@1+ (1,0) [0|1] ""  MBMU,PC
 SG_ TMS_MakeBMSStop_43 : 6|1@1+ (1,0) [0|1] ""  MBMU,PC
 SG_ TMS_HVRealyState_43 : 7|1@1+ (1,0) [0|1] ""  MBMU,PC
 SG_ TMS_FaultCode_43 : 8|6@1+ (1,0) [0|63] ""  MBMU,PC
 SG_ TMS_FaultLevel_43 : 14|2@1+ (1,0) [0|3] ""  MBMU,PC
 SG_ B2T_TmptSetPoint_43 : 16|8@1+ (1,-50) [-50|210] "℃"  MBMU,PC
 SG_ TMS_OutWaterTemp_43 : 24|8@1+ (1,-50) [-50|210] "℃"  MBMU,PC
 SG_ TMS_BackWaterTemp_43 : 32|8@1+ (1,-50) [-50|210] "℃"  MBMU,PC
 SG_ TMS_EnvTemp_43 : 40|8@1+ (1,-50) [-50|210] "℃"  MBMU,PC
 SG_ TMS_RequestPower_43 : 48|8@1+ (0.1,0) [0|100] "Kw"  MBMU,PC
 SG_ STMS_ThrmStopReason_43 : 56|3@1+ (1,0) [0|3] ""  MBMU,PC

BO_ 2332688236 S2A_LiquidInfo__44: 8 SBMU
 SG_ B2T_ControlMode_44 : 0|2@1+ (1,0) [0|3] ""  MBMU,PC
 SG_ TMS_RunState_44 : 2|2@1+ (1,0) [0|3] ""  MBMU,PC
 SG_ TMS_CommuFault_44 : 4|1@1+ (1,0) [0|1] ""  MBMU,PC
 SG_ TMS_ModeConflict_44 : 5|1@1+ (1,0) [0|1] ""  MBMU,PC
 SG_ TMS_MakeBMSStop_44 : 6|1@1+ (1,0) [0|1] ""  MBMU,PC
 SG_ TMS_HVRealyState_44 : 7|1@1+ (1,0) [0|1] ""  MBMU,PC
 SG_ TMS_FaultCode_44 : 8|6@1+ (1,0) [0|63] ""  MBMU,PC
 SG_ TMS_FaultLevel_44 : 14|2@1+ (1,0) [0|3] ""  MBMU,PC
 SG_ B2T_TmptSetPoint_44 : 16|8@1+ (1,-50) [-50|210] "℃"  MBMU,PC
 SG_ TMS_OutWaterTemp_44 : 24|8@1+ (1,-50) [-50|210] "℃"  MBMU,PC
 SG_ TMS_BackWaterTemp_44 : 32|8@1+ (1,-50) [-50|210] "℃"  MBMU,PC
 SG_ TMS_EnvTemp_44 : 40|8@1+ (1,-50) [-50|210] "℃"  MBMU,PC
 SG_ TMS_RequestPower_44 : 48|8@1+ (0.1,0) [0|100] "Kw"  MBMU,PC
 SG_ STMS_ThrmStopReason_44 : 56|3@1+ (1,0) [0|3] ""  MBMU,PC

BO_ 2332688237 S2A_LiquidInfo__45: 8 SBMU
 SG_ B2T_ControlMode_45 : 0|2@1+ (1,0) [0|3] ""  MBMU,PC
 SG_ TMS_RunState_45 : 2|2@1+ (1,0) [0|3] ""  MBMU,PC
 SG_ TMS_CommuFault_45 : 4|1@1+ (1,0) [0|1] ""  MBMU,PC
 SG_ TMS_ModeConflict_45 : 5|1@1+ (1,0) [0|1] ""  MBMU,PC
 SG_ TMS_MakeBMSStop_45 : 6|1@1+ (1,0) [0|1] ""  MBMU,PC
 SG_ TMS_HVRealyState_45 : 7|1@1+ (1,0) [0|1] ""  MBMU,PC
 SG_ TMS_FaultCode_45 : 8|6@1+ (1,0) [0|63] ""  MBMU,PC
 SG_ TMS_FaultLevel_45 : 14|2@1+ (1,0) [0|3] ""  MBMU,PC
 SG_ B2T_TmptSetPoint_45 : 16|8@1+ (1,-50) [-50|210] "℃"  MBMU,PC
 SG_ TMS_OutWaterTemp_45 : 24|8@1+ (1,-50) [-50|210] "℃"  MBMU,PC
 SG_ TMS_BackWaterTemp_45 : 32|8@1+ (1,-50) [-50|210] "℃"  MBMU,PC
 SG_ TMS_EnvTemp_45 : 40|8@1+ (1,-50) [-50|210] "℃"  MBMU,PC
 SG_ TMS_RequestPower_45 : 48|8@1+ (0.1,0) [0|100] "Kw"  MBMU,PC
 SG_ STMS_ThrmStopReason_45 : 56|3@1+ (1,0) [0|3] ""  MBMU,PC

BO_ 2332688238 S2A_LiquidInfo__46: 8 SBMU
 SG_ B2T_ControlMode_46 : 0|2@1+ (1,0) [0|3] ""  MBMU,PC
 SG_ TMS_RunState_46 : 2|2@1+ (1,0) [0|3] ""  MBMU,PC
 SG_ TMS_CommuFault_46 : 4|1@1+ (1,0) [0|1] ""  MBMU,PC
 SG_ TMS_ModeConflict_46 : 5|1@1+ (1,0) [0|1] ""  MBMU,PC
 SG_ TMS_MakeBMSStop_46 : 6|1@1+ (1,0) [0|1] ""  MBMU,PC
 SG_ TMS_HVRealyState_46 : 7|1@1+ (1,0) [0|1] ""  MBMU,PC
 SG_ TMS_FaultCode_46 : 8|6@1+ (1,0) [0|63] ""  MBMU,PC
 SG_ TMS_FaultLevel_46 : 14|2@1+ (1,0) [0|3] ""  MBMU,PC
 SG_ B2T_TmptSetPoint_46 : 16|8@1+ (1,-50) [-50|210] "℃"  MBMU,PC
 SG_ TMS_OutWaterTemp_46 : 24|8@1+ (1,-50) [-50|210] "℃"  MBMU,PC
 SG_ TMS_BackWaterTemp_46 : 32|8@1+ (1,-50) [-50|210] "℃"  MBMU,PC
 SG_ TMS_EnvTemp_46 : 40|8@1+ (1,-50) [-50|210] "℃"  MBMU,PC
 SG_ TMS_RequestPower_46 : 48|8@1+ (0.1,0) [0|100] "Kw"  MBMU,PC
 SG_ STMS_ThrmStopReason_46 : 56|3@1+ (1,0) [0|3] ""  MBMU,PC

BO_ 2332688239 S2A_LiquidInfo__47: 8 SBMU
 SG_ B2T_ControlMode_47 : 0|2@1+ (1,0) [0|3] ""  MBMU,PC
 SG_ TMS_RunState_47 : 2|2@1+ (1,0) [0|3] ""  MBMU,PC
 SG_ TMS_CommuFault_47 : 4|1@1+ (1,0) [0|1] ""  MBMU,PC
 SG_ TMS_ModeConflict_47 : 5|1@1+ (1,0) [0|1] ""  MBMU,PC
 SG_ TMS_MakeBMSStop_47 : 6|1@1+ (1,0) [0|1] ""  MBMU,PC
 SG_ TMS_HVRealyState_47 : 7|1@1+ (1,0) [0|1] ""  MBMU,PC
 SG_ TMS_FaultCode_47 : 8|6@1+ (1,0) [0|63] ""  MBMU,PC
 SG_ TMS_FaultLevel_47 : 14|2@1+ (1,0) [0|3] ""  MBMU,PC
 SG_ B2T_TmptSetPoint_47 : 16|8@1+ (1,-50) [-50|210] "℃"  MBMU,PC
 SG_ TMS_OutWaterTemp_47 : 24|8@1+ (1,-50) [-50|210] "℃"  MBMU,PC
 SG_ TMS_BackWaterTemp_47 : 32|8@1+ (1,-50) [-50|210] "℃"  MBMU,PC
 SG_ TMS_EnvTemp_47 : 40|8@1+ (1,-50) [-50|210] "℃"  MBMU,PC
 SG_ TMS_RequestPower_47 : 48|8@1+ (0.1,0) [0|100] "Kw"  MBMU,PC
 SG_ STMS_ThrmStopReason_47 : 56|3@1+ (1,0) [0|3] ""  MBMU,PC

BO_ 2332688240 S2A_LiquidInfo__48: 8 SBMU
 SG_ B2T_ControlMode_48 : 0|2@1+ (1,0) [0|3] ""  MBMU,PC
 SG_ TMS_RunState_48 : 2|2@1+ (1,0) [0|3] ""  MBMU,PC
 SG_ TMS_CommuFault_48 : 4|1@1+ (1,0) [0|1] ""  MBMU,PC
 SG_ TMS_ModeConflict_48 : 5|1@1+ (1,0) [0|1] ""  MBMU,PC
 SG_ TMS_MakeBMSStop_48 : 6|1@1+ (1,0) [0|1] ""  MBMU,PC
 SG_ TMS_HVRealyState_48 : 7|1@1+ (1,0) [0|1] ""  MBMU,PC
 SG_ TMS_FaultCode_48 : 8|6@1+ (1,0) [0|63] ""  MBMU,PC
 SG_ TMS_FaultLevel_48 : 14|2@1+ (1,0) [0|3] ""  MBMU,PC
 SG_ B2T_TmptSetPoint_48 : 16|8@1+ (1,-50) [-50|210] "℃"  MBMU,PC
 SG_ TMS_OutWaterTemp_48 : 24|8@1+ (1,-50) [-50|210] "℃"  MBMU,PC
 SG_ TMS_BackWaterTemp_48 : 32|8@1+ (1,-50) [-50|210] "℃"  MBMU,PC
 SG_ TMS_EnvTemp_48 : 40|8@1+ (1,-50) [-50|210] "℃"  MBMU,PC
 SG_ TMS_RequestPower_48 : 48|8@1+ (0.1,0) [0|100] "Kw"  MBMU,PC
 SG_ STMS_ThrmStopReason_48 : 56|3@1+ (1,0) [0|3] ""  MBMU,PC

BO_ 2332688241 S2A_LiquidInfo__49: 8 SBMU
 SG_ B2T_ControlMode_49 : 0|2@1+ (1,0) [0|3] ""  MBMU,PC
 SG_ TMS_RunState_49 : 2|2@1+ (1,0) [0|3] ""  MBMU,PC
 SG_ TMS_CommuFault_49 : 4|1@1+ (1,0) [0|1] ""  MBMU,PC
 SG_ TMS_ModeConflict_49 : 5|1@1+ (1,0) [0|1] ""  MBMU,PC
 SG_ TMS_MakeBMSStop_49 : 6|1@1+ (1,0) [0|1] ""  MBMU,PC
 SG_ TMS_HVRealyState_49 : 7|1@1+ (1,0) [0|1] ""  MBMU,PC
 SG_ TMS_FaultCode_49 : 8|6@1+ (1,0) [0|63] ""  MBMU,PC
 SG_ TMS_FaultLevel_49 : 14|2@1+ (1,0) [0|3] ""  MBMU,PC
 SG_ B2T_TmptSetPoint_49 : 16|8@1+ (1,-50) [-50|210] "℃"  MBMU,PC
 SG_ TMS_OutWaterTemp_49 : 24|8@1+ (1,-50) [-50|210] "℃"  MBMU,PC
 SG_ TMS_BackWaterTemp_49 : 32|8@1+ (1,-50) [-50|210] "℃"  MBMU,PC
 SG_ TMS_EnvTemp_49 : 40|8@1+ (1,-50) [-50|210] "℃"  MBMU,PC
 SG_ TMS_RequestPower_49 : 48|8@1+ (0.1,0) [0|100] "Kw"  MBMU,PC
 SG_ STMS_ThrmStopReason_49 : 56|3@1+ (1,0) [0|3] ""  MBMU,PC

BO_ 2332688242 S2A_LiquidInfo__50: 8 SBMU
 SG_ B2T_ControlMode_50 : 0|2@1+ (1,0) [0|3] ""  MBMU,PC
 SG_ TMS_RunState_50 : 2|2@1+ (1,0) [0|3] ""  MBMU,PC
 SG_ TMS_CommuFault_50 : 4|1@1+ (1,0) [0|1] ""  MBMU,PC
 SG_ TMS_ModeConflict_50 : 5|1@1+ (1,0) [0|1] ""  MBMU,PC
 SG_ TMS_MakeBMSStop_50 : 6|1@1+ (1,0) [0|1] ""  MBMU,PC
 SG_ TMS_HVRealyState_50 : 7|1@1+ (1,0) [0|1] ""  MBMU,PC
 SG_ TMS_FaultCode_50 : 8|6@1+ (1,0) [0|63] ""  MBMU,PC
 SG_ TMS_FaultLevel_50 : 14|2@1+ (1,0) [0|3] ""  MBMU,PC
 SG_ B2T_TmptSetPoint_50 : 16|8@1+ (1,-50) [-50|210] "℃"  MBMU,PC
 SG_ TMS_OutWaterTemp_50 : 24|8@1+ (1,-50) [-50|210] "℃"  MBMU,PC
 SG_ TMS_BackWaterTemp_50 : 32|8@1+ (1,-50) [-50|210] "℃"  MBMU,PC
 SG_ TMS_EnvTemp_50 : 40|8@1+ (1,-50) [-50|210] "℃"  MBMU,PC
 SG_ TMS_RequestPower_50 : 48|8@1+ (0.1,0) [0|100] "Kw"  MBMU,PC
 SG_ STMS_ThrmStopReason_50 : 56|3@1+ (1,0) [0|3] ""  MBMU,PC

BO_ 2332688243 S2A_LiquidInfo__51: 8 SBMU
 SG_ B2T_ControlMode_51 : 0|2@1+ (1,0) [0|3] ""  MBMU,PC
 SG_ TMS_RunState_51 : 2|2@1+ (1,0) [0|3] ""  MBMU,PC
 SG_ TMS_CommuFault_51 : 4|1@1+ (1,0) [0|1] ""  MBMU,PC
 SG_ TMS_ModeConflict_51 : 5|1@1+ (1,0) [0|1] ""  MBMU,PC
 SG_ TMS_MakeBMSStop_51 : 6|1@1+ (1,0) [0|1] ""  MBMU,PC
 SG_ TMS_HVRealyState_51 : 7|1@1+ (1,0) [0|1] ""  MBMU,PC
 SG_ TMS_FaultCode_51 : 8|6@1+ (1,0) [0|63] ""  MBMU,PC
 SG_ TMS_FaultLevel_51 : 14|2@1+ (1,0) [0|3] ""  MBMU,PC
 SG_ B2T_TmptSetPoint_51 : 16|8@1+ (1,-50) [-50|210] "℃"  MBMU,PC
 SG_ TMS_OutWaterTemp_51 : 24|8@1+ (1,-50) [-50|210] "℃"  MBMU,PC
 SG_ TMS_BackWaterTemp_51 : 32|8@1+ (1,-50) [-50|210] "℃"  MBMU,PC
 SG_ TMS_EnvTemp_51 : 40|8@1+ (1,-50) [-50|210] "℃"  MBMU,PC
 SG_ TMS_RequestPower_51 : 48|8@1+ (0.1,0) [0|100] "Kw"  MBMU,PC
 SG_ STMS_ThrmStopReason_51 : 56|3@1+ (1,0) [0|3] ""  MBMU,PC

BO_ 2332688244 S2A_LiquidInfo__52: 8 SBMU
 SG_ B2T_ControlMode_52 : 0|2@1+ (1,0) [0|3] ""  MBMU,PC
 SG_ TMS_RunState_52 : 2|2@1+ (1,0) [0|3] ""  MBMU,PC
 SG_ TMS_CommuFault_52 : 4|1@1+ (1,0) [0|1] ""  MBMU,PC
 SG_ TMS_ModeConflict_52 : 5|1@1+ (1,0) [0|1] ""  MBMU,PC
 SG_ TMS_MakeBMSStop_52 : 6|1@1+ (1,0) [0|1] ""  MBMU,PC
 SG_ TMS_HVRealyState_52 : 7|1@1+ (1,0) [0|1] ""  MBMU,PC
 SG_ TMS_FaultCode_52 : 8|6@1+ (1,0) [0|63] ""  MBMU,PC
 SG_ TMS_FaultLevel_52 : 14|2@1+ (1,0) [0|3] ""  MBMU,PC
 SG_ B2T_TmptSetPoint_52 : 16|8@1+ (1,-50) [-50|210] "℃"  MBMU,PC
 SG_ TMS_OutWaterTemp_52 : 24|8@1+ (1,-50) [-50|210] "℃"  MBMU,PC
 SG_ TMS_BackWaterTemp_52 : 32|8@1+ (1,-50) [-50|210] "℃"  MBMU,PC
 SG_ TMS_EnvTemp_52 : 40|8@1+ (1,-50) [-50|210] "℃"  MBMU,PC
 SG_ TMS_RequestPower_52 : 48|8@1+ (0.1,0) [0|100] "Kw"  MBMU,PC
 SG_ STMS_ThrmStopReason_52 : 56|3@1+ (1,0) [0|3] ""  MBMU,PC

BO_ 2332688245 S2A_LiquidInfo__53: 8 SBMU
 SG_ B2T_ControlMode_53 : 0|2@1+ (1,0) [0|3] ""  MBMU,PC
 SG_ TMS_RunState_53 : 2|2@1+ (1,0) [0|3] ""  MBMU,PC
 SG_ TMS_CommuFault_53 : 4|1@1+ (1,0) [0|1] ""  MBMU,PC
 SG_ TMS_ModeConflict_53 : 5|1@1+ (1,0) [0|1] ""  MBMU,PC
 SG_ TMS_MakeBMSStop_53 : 6|1@1+ (1,0) [0|1] ""  MBMU,PC
 SG_ TMS_HVRealyState_53 : 7|1@1+ (1,0) [0|1] ""  MBMU,PC
 SG_ TMS_FaultCode_53 : 8|6@1+ (1,0) [0|63] ""  MBMU,PC
 SG_ TMS_FaultLevel_53 : 14|2@1+ (1,0) [0|3] ""  MBMU,PC
 SG_ B2T_TmptSetPoint_53 : 16|8@1+ (1,-50) [-50|210] "℃"  MBMU,PC
 SG_ TMS_OutWaterTemp_53 : 24|8@1+ (1,-50) [-50|210] "℃"  MBMU,PC
 SG_ TMS_BackWaterTemp_53 : 32|8@1+ (1,-50) [-50|210] "℃"  MBMU,PC
 SG_ TMS_EnvTemp_53 : 40|8@1+ (1,-50) [-50|210] "℃"  MBMU,PC
 SG_ TMS_RequestPower_53 : 48|8@1+ (0.1,0) [0|100] "Kw"  MBMU,PC
 SG_ STMS_ThrmStopReason_53 : 56|3@1+ (1,0) [0|3] ""  MBMU,PC

BO_ 2332688246 S2A_LiquidInfo__54: 8 SBMU
 SG_ B2T_ControlMode_54 : 0|2@1+ (1,0) [0|3] ""  MBMU,PC
 SG_ TMS_RunState_54 : 2|2@1+ (1,0) [0|3] ""  MBMU,PC
 SG_ TMS_CommuFault_54 : 4|1@1+ (1,0) [0|1] ""  MBMU,PC
 SG_ TMS_ModeConflict_54 : 5|1@1+ (1,0) [0|1] ""  MBMU,PC
 SG_ TMS_MakeBMSStop_54 : 6|1@1+ (1,0) [0|1] ""  MBMU,PC
 SG_ TMS_HVRealyState_54 : 7|1@1+ (1,0) [0|1] ""  MBMU,PC
 SG_ TMS_FaultCode_54 : 8|6@1+ (1,0) [0|63] ""  MBMU,PC
 SG_ TMS_FaultLevel_54 : 14|2@1+ (1,0) [0|3] ""  MBMU,PC
 SG_ B2T_TmptSetPoint_54 : 16|8@1+ (1,-50) [-50|210] "℃"  MBMU,PC
 SG_ TMS_OutWaterTemp_54 : 24|8@1+ (1,-50) [-50|210] "℃"  MBMU,PC
 SG_ TMS_BackWaterTemp_54 : 32|8@1+ (1,-50) [-50|210] "℃"  MBMU,PC
 SG_ TMS_EnvTemp_54 : 40|8@1+ (1,-50) [-50|210] "℃"  MBMU,PC
 SG_ TMS_RequestPower_54 : 48|8@1+ (0.1,0) [0|100] "Kw"  MBMU,PC
 SG_ STMS_ThrmStopReason_54 : 56|3@1+ (1,0) [0|3] ""  MBMU,PC

BO_ 2332688247 S2A_LiquidInfo__55: 8 SBMU
 SG_ B2T_ControlMode_55 : 0|2@1+ (1,0) [0|3] ""  MBMU,PC
 SG_ TMS_RunState_55 : 2|2@1+ (1,0) [0|3] ""  MBMU,PC
 SG_ TMS_CommuFault_55 : 4|1@1+ (1,0) [0|1] ""  MBMU,PC
 SG_ TMS_ModeConflict_55 : 5|1@1+ (1,0) [0|1] ""  MBMU,PC
 SG_ TMS_MakeBMSStop_55 : 6|1@1+ (1,0) [0|1] ""  MBMU,PC
 SG_ TMS_HVRealyState_55 : 7|1@1+ (1,0) [0|1] ""  MBMU,PC
 SG_ TMS_FaultCode_55 : 8|6@1+ (1,0) [0|63] ""  MBMU,PC
 SG_ TMS_FaultLevel_55 : 14|2@1+ (1,0) [0|3] ""  MBMU,PC
 SG_ B2T_TmptSetPoint_55 : 16|8@1+ (1,-50) [-50|210] "℃"  MBMU,PC
 SG_ TMS_OutWaterTemp_55 : 24|8@1+ (1,-50) [-50|210] "℃"  MBMU,PC
 SG_ TMS_BackWaterTemp_55 : 32|8@1+ (1,-50) [-50|210] "℃"  MBMU,PC
 SG_ TMS_EnvTemp_55 : 40|8@1+ (1,-50) [-50|210] "℃"  MBMU,PC
 SG_ TMS_RequestPower_55 : 48|8@1+ (0.1,0) [0|100] "Kw"  MBMU,PC
 SG_ STMS_ThrmStopReason_55 : 56|3@1+ (1,0) [0|3] ""  MBMU,PC

BO_ 2332688248 S2A_LiquidInfo__56: 8 SBMU
 SG_ B2T_ControlMode_56 : 0|2@1+ (1,0) [0|3] ""  MBMU,PC
 SG_ TMS_RunState_56 : 2|2@1+ (1,0) [0|3] ""  MBMU,PC
 SG_ TMS_CommuFault_56 : 4|1@1+ (1,0) [0|1] ""  MBMU,PC
 SG_ TMS_ModeConflict_56 : 5|1@1+ (1,0) [0|1] ""  MBMU,PC
 SG_ TMS_MakeBMSStop_56 : 6|1@1+ (1,0) [0|1] ""  MBMU,PC
 SG_ TMS_HVRealyState_56 : 7|1@1+ (1,0) [0|1] ""  MBMU,PC
 SG_ TMS_FaultCode_56 : 8|6@1+ (1,0) [0|63] ""  MBMU,PC
 SG_ TMS_FaultLevel_56 : 14|2@1+ (1,0) [0|3] ""  MBMU,PC
 SG_ B2T_TmptSetPoint_56 : 16|8@1+ (1,-50) [-50|210] "℃"  MBMU,PC
 SG_ TMS_OutWaterTemp_56 : 24|8@1+ (1,-50) [-50|210] "℃"  MBMU,PC
 SG_ TMS_BackWaterTemp_56 : 32|8@1+ (1,-50) [-50|210] "℃"  MBMU,PC
 SG_ TMS_EnvTemp_56 : 40|8@1+ (1,-50) [-50|210] "℃"  MBMU,PC
 SG_ TMS_RequestPower_56 : 48|8@1+ (0.1,0) [0|100] "Kw"  MBMU,PC
 SG_ STMS_ThrmStopReason_56 : 56|3@1+ (1,0) [0|3] ""  MBMU,PC

BO_ 2332688249 S2A_LiquidInfo__57: 8 SBMU
 SG_ B2T_ControlMode_57 : 0|2@1+ (1,0) [0|3] ""  MBMU,PC
 SG_ TMS_RunState_57 : 2|2@1+ (1,0) [0|3] ""  MBMU,PC
 SG_ TMS_CommuFault_57 : 4|1@1+ (1,0) [0|1] ""  MBMU,PC
 SG_ TMS_ModeConflict_57 : 5|1@1+ (1,0) [0|1] ""  MBMU,PC
 SG_ TMS_MakeBMSStop_57 : 6|1@1+ (1,0) [0|1] ""  MBMU,PC
 SG_ TMS_HVRealyState_57 : 7|1@1+ (1,0) [0|1] ""  MBMU,PC
 SG_ TMS_FaultCode_57 : 8|6@1+ (1,0) [0|63] ""  MBMU,PC
 SG_ TMS_FaultLevel_57 : 14|2@1+ (1,0) [0|3] ""  MBMU,PC
 SG_ B2T_TmptSetPoint_57 : 16|8@1+ (1,-50) [-50|210] "℃"  MBMU,PC
 SG_ TMS_OutWaterTemp_57 : 24|8@1+ (1,-50) [-50|210] "℃"  MBMU,PC
 SG_ TMS_BackWaterTemp_57 : 32|8@1+ (1,-50) [-50|210] "℃"  MBMU,PC
 SG_ TMS_EnvTemp_57 : 40|8@1+ (1,-50) [-50|210] "℃"  MBMU,PC
 SG_ TMS_RequestPower_57 : 48|8@1+ (0.1,0) [0|100] "Kw"  MBMU,PC
 SG_ STMS_ThrmStopReason_57 : 56|3@1+ (1,0) [0|3] ""  MBMU,PC

BO_ 2332688250 S2A_LiquidInfo__58: 8 SBMU
 SG_ B2T_ControlMode_58 : 0|2@1+ (1,0) [0|3] ""  MBMU,PC
 SG_ TMS_RunState_58 : 2|2@1+ (1,0) [0|3] ""  MBMU,PC
 SG_ TMS_CommuFault_58 : 4|1@1+ (1,0) [0|1] ""  MBMU,PC
 SG_ TMS_ModeConflict_58 : 5|1@1+ (1,0) [0|1] ""  MBMU,PC
 SG_ TMS_MakeBMSStop_58 : 6|1@1+ (1,0) [0|1] ""  MBMU,PC
 SG_ TMS_HVRealyState_58 : 7|1@1+ (1,0) [0|1] ""  MBMU,PC
 SG_ TMS_FaultCode_58 : 8|6@1+ (1,0) [0|63] ""  MBMU,PC
 SG_ TMS_FaultLevel_58 : 14|2@1+ (1,0) [0|3] ""  MBMU,PC
 SG_ B2T_TmptSetPoint_58 : 16|8@1+ (1,-50) [-50|210] "℃"  MBMU,PC
 SG_ TMS_OutWaterTemp_58 : 24|8@1+ (1,-50) [-50|210] "℃"  MBMU,PC
 SG_ TMS_BackWaterTemp_58 : 32|8@1+ (1,-50) [-50|210] "℃"  MBMU,PC
 SG_ TMS_EnvTemp_58 : 40|8@1+ (1,-50) [-50|210] "℃"  MBMU,PC
 SG_ TMS_RequestPower_58 : 48|8@1+ (0.1,0) [0|100] "Kw"  MBMU,PC
 SG_ STMS_ThrmStopReason_58 : 56|3@1+ (1,0) [0|3] ""  MBMU,PC

BO_ 2332688251 S2A_LiquidInfo__59: 8 SBMU
 SG_ B2T_ControlMode_59 : 0|2@1+ (1,0) [0|3] ""  MBMU,PC
 SG_ TMS_RunState_59 : 2|2@1+ (1,0) [0|3] ""  MBMU,PC
 SG_ TMS_CommuFault_59 : 4|1@1+ (1,0) [0|1] ""  MBMU,PC
 SG_ TMS_ModeConflict_59 : 5|1@1+ (1,0) [0|1] ""  MBMU,PC
 SG_ TMS_MakeBMSStop_59 : 6|1@1+ (1,0) [0|1] ""  MBMU,PC
 SG_ TMS_HVRealyState_59 : 7|1@1+ (1,0) [0|1] ""  MBMU,PC
 SG_ TMS_FaultCode_59 : 8|6@1+ (1,0) [0|63] ""  MBMU,PC
 SG_ TMS_FaultLevel_59 : 14|2@1+ (1,0) [0|3] ""  MBMU,PC
 SG_ B2T_TmptSetPoint_59 : 16|8@1+ (1,-50) [-50|210] "℃"  MBMU,PC
 SG_ TMS_OutWaterTemp_59 : 24|8@1+ (1,-50) [-50|210] "℃"  MBMU,PC
 SG_ TMS_BackWaterTemp_59 : 32|8@1+ (1,-50) [-50|210] "℃"  MBMU,PC
 SG_ TMS_EnvTemp_59 : 40|8@1+ (1,-50) [-50|210] "℃"  MBMU,PC
 SG_ TMS_RequestPower_59 : 48|8@1+ (0.1,0) [0|100] "Kw"  MBMU,PC
 SG_ STMS_ThrmStopReason_59 : 56|3@1+ (1,0) [0|3] ""  MBMU,PC

BO_ 2332688252 S2A_LiquidInfo__60: 8 SBMU
 SG_ B2T_ControlMode_60 : 0|2@1+ (1,0) [0|3] ""  MBMU,PC
 SG_ TMS_RunState_60 : 2|2@1+ (1,0) [0|3] ""  MBMU,PC
 SG_ TMS_CommuFault_60 : 4|1@1+ (1,0) [0|1] ""  MBMU,PC
 SG_ TMS_ModeConflict_60 : 5|1@1+ (1,0) [0|1] ""  MBMU,PC
 SG_ TMS_MakeBMSStop_60 : 6|1@1+ (1,0) [0|1] ""  MBMU,PC
 SG_ TMS_HVRealyState_60 : 7|1@1+ (1,0) [0|1] ""  MBMU,PC
 SG_ TMS_FaultCode_60 : 8|6@1+ (1,0) [0|63] ""  MBMU,PC
 SG_ TMS_FaultLevel_60 : 14|2@1+ (1,0) [0|3] ""  MBMU,PC
 SG_ B2T_TmptSetPoint_60 : 16|8@1+ (1,-50) [-50|210] "℃"  MBMU,PC
 SG_ TMS_OutWaterTemp_60 : 24|8@1+ (1,-50) [-50|210] "℃"  MBMU,PC
 SG_ TMS_BackWaterTemp_60 : 32|8@1+ (1,-50) [-50|210] "℃"  MBMU,PC
 SG_ TMS_EnvTemp_60 : 40|8@1+ (1,-50) [-50|210] "℃"  MBMU,PC
 SG_ TMS_RequestPower_60 : 48|8@1+ (0.1,0) [0|100] "Kw"  MBMU,PC
 SG_ STMS_ThrmStopReason_60 : 56|3@1+ (1,0) [0|3] ""  MBMU,PC

BO_ 2332688253 S2A_LiquidInfo__61: 8 SBMU
 SG_ B2T_ControlMode_61 : 0|2@1+ (1,0) [0|3] ""  MBMU,PC
 SG_ TMS_RunState_61 : 2|2@1+ (1,0) [0|3] ""  MBMU,PC
 SG_ TMS_CommuFault_61 : 4|1@1+ (1,0) [0|1] ""  MBMU,PC
 SG_ TMS_ModeConflict_61 : 5|1@1+ (1,0) [0|1] ""  MBMU,PC
 SG_ TMS_MakeBMSStop_61 : 6|1@1+ (1,0) [0|1] ""  MBMU,PC
 SG_ TMS_HVRealyState_61 : 7|1@1+ (1,0) [0|1] ""  MBMU,PC
 SG_ TMS_FaultCode_61 : 8|6@1+ (1,0) [0|63] ""  MBMU,PC
 SG_ TMS_FaultLevel_61 : 14|2@1+ (1,0) [0|3] ""  MBMU,PC
 SG_ B2T_TmptSetPoint_61 : 16|8@1+ (1,-50) [-50|210] "℃"  MBMU,PC
 SG_ TMS_OutWaterTemp_61 : 24|8@1+ (1,-50) [-50|210] "℃"  MBMU,PC
 SG_ TMS_BackWaterTemp_61 : 32|8@1+ (1,-50) [-50|210] "℃"  MBMU,PC
 SG_ TMS_EnvTemp_61 : 40|8@1+ (1,-50) [-50|210] "℃"  MBMU,PC
 SG_ TMS_RequestPower_61 : 48|8@1+ (0.1,0) [0|100] "Kw"  MBMU,PC
 SG_ STMS_ThrmStopReason_61 : 56|3@1+ (1,0) [0|3] ""  MBMU,PC

BO_ 2332688254 S2A_LiquidInfo__62: 8 SBMU
 SG_ B2T_ControlMode_62 : 0|2@1+ (1,0) [0|3] ""  MBMU,PC
 SG_ TMS_RunState_62 : 2|2@1+ (1,0) [0|3] ""  MBMU,PC
 SG_ TMS_CommuFault_62 : 4|1@1+ (1,0) [0|1] ""  MBMU,PC
 SG_ TMS_ModeConflict_62 : 5|1@1+ (1,0) [0|1] ""  MBMU,PC
 SG_ TMS_MakeBMSStop_62 : 6|1@1+ (1,0) [0|1] ""  MBMU,PC
 SG_ TMS_HVRealyState_62 : 7|1@1+ (1,0) [0|1] ""  MBMU,PC
 SG_ TMS_FaultCode_62 : 8|6@1+ (1,0) [0|63] ""  MBMU,PC
 SG_ TMS_FaultLevel_62 : 14|2@1+ (1,0) [0|3] ""  MBMU,PC
 SG_ B2T_TmptSetPoint_62 : 16|8@1+ (1,-50) [-50|210] "℃"  MBMU,PC
 SG_ TMS_OutWaterTemp_62 : 24|8@1+ (1,-50) [-50|210] "℃"  MBMU,PC
 SG_ TMS_BackWaterTemp_62 : 32|8@1+ (1,-50) [-50|210] "℃"  MBMU,PC
 SG_ TMS_EnvTemp_62 : 40|8@1+ (1,-50) [-50|210] "℃"  MBMU,PC
 SG_ TMS_RequestPower_62 : 48|8@1+ (0.1,0) [0|100] "Kw"  MBMU,PC
 SG_ STMS_ThrmStopReason_62 : 56|3@1+ (1,0) [0|3] ""  MBMU,PC

BO_ 2332688255 S2A_LiquidInfo__63: 8 SBMU
 SG_ B2T_ControlMode_63 : 0|2@1+ (1,0) [0|3] ""  MBMU,PC
 SG_ TMS_RunState_63 : 2|2@1+ (1,0) [0|3] ""  MBMU,PC
 SG_ TMS_CommuFault_63 : 4|1@1+ (1,0) [0|1] ""  MBMU,PC
 SG_ TMS_ModeConflict_63 : 5|1@1+ (1,0) [0|1] ""  MBMU,PC
 SG_ TMS_MakeBMSStop_63 : 6|1@1+ (1,0) [0|1] ""  MBMU,PC
 SG_ TMS_HVRealyState_63 : 7|1@1+ (1,0) [0|1] ""  MBMU,PC
 SG_ TMS_FaultCode_63 : 8|6@1+ (1,0) [0|63] ""  MBMU,PC
 SG_ TMS_FaultLevel_63 : 14|2@1+ (1,0) [0|3] ""  MBMU,PC
 SG_ B2T_TmptSetPoint_63 : 16|8@1+ (1,-50) [-50|210] "℃"  MBMU,PC
 SG_ TMS_OutWaterTemp_63 : 24|8@1+ (1,-50) [-50|210] "℃"  MBMU,PC
 SG_ TMS_BackWaterTemp_63 : 32|8@1+ (1,-50) [-50|210] "℃"  MBMU,PC
 SG_ TMS_EnvTemp_63 : 40|8@1+ (1,-50) [-50|210] "℃"  MBMU,PC
 SG_ TMS_RequestPower_63 : 48|8@1+ (0.1,0) [0|100] "Kw"  MBMU,PC
 SG_ STMS_ThrmStopReason_63 : 56|3@1+ (1,0) [0|3] ""  MBMU,PC

BO_ 2332753729 S2A_DryContact__01: 8 SBMU
 SG_ FireFault_Level1_01 : 0|1@1+ (1,0) [0|1] ""  MBMU,PC
 SG_ FireFault_Level2_01 : 1|1@1+ (1,0) [0|1] ""  MBMU,PC
 SG_ TempState_01 : 2|1@1+ (1,0) [0|1] ""  MBMU,PC
 SG_ FogState_01 : 3|1@1+ (1,0) [0|1] ""  MBMU,PC
 SG_ AerosolState_01 : 4|1@1+ (1,0) [0|1] ""  MBMU,PC
 SG_ AerosolFaultState_01 : 5|2@1+ (1,0) [0|3] ""  MBMU,PC
 SG_ DoorState_01 : 7|1@1+ (1,0) [0|1] ""  MBMU,PC
 SG_ ControlBoxFanState_01 : 8|1@1+ (1,0) [0|1] ""  MBMU,PC
 SG_ ControlBoxTempHighWarning_01 : 9|1@1+ (1,0) [0|1] ""  MBMU,PC
 SG_ PowerSWState_01 : 10|1@1+ (1,0) [0|1] ""  MBMU,PC
 SG_ FaultClearCommand_01 : 11|1@1+ (1,0) [0|1] ""  MBMU,PC

BO_ 2332753730 S2A_DryContact__02: 8 SBMU
 SG_ FireFault_Level1_02 : 0|1@1+ (1,0) [0|1] ""  MBMU,PC
 SG_ FireFault_Level2_02 : 1|1@1+ (1,0) [0|1] ""  MBMU,PC
 SG_ TempState_02 : 2|1@1+ (1,0) [0|1] ""  MBMU,PC
 SG_ FogState_02 : 3|1@1+ (1,0) [0|1] ""  MBMU,PC
 SG_ AerosolState_02 : 4|1@1+ (1,0) [0|1] ""  MBMU,PC
 SG_ AerosolFaultState_02 : 5|2@1+ (1,0) [0|3] ""  MBMU,PC
 SG_ DoorState_02 : 7|1@1+ (1,0) [0|1] ""  MBMU,PC
 SG_ ControlBoxFanState_02 : 8|1@1+ (1,0) [0|1] ""  MBMU,PC
 SG_ ControlBoxTempHighWarning_02 : 9|1@1+ (1,0) [0|1] ""  MBMU,PC
 SG_ PowerSWState_02 : 10|1@1+ (1,0) [0|1] ""  MBMU,PC
 SG_ FaultClearCommand_02 : 11|1@1+ (1,0) [0|1] ""  MBMU,PC

BO_ 2332753731 S2A_DryContact__03: 8 SBMU
 SG_ FireFault_Level1_03 : 0|1@1+ (1,0) [0|1] ""  MBMU,PC
 SG_ FireFault_Level2_03 : 1|1@1+ (1,0) [0|1] ""  MBMU,PC
 SG_ TempState_03 : 2|1@1+ (1,0) [0|1] ""  MBMU,PC
 SG_ FogState_03 : 3|1@1+ (1,0) [0|1] ""  MBMU,PC
 SG_ AerosolState_03 : 4|1@1+ (1,0) [0|1] ""  MBMU,PC
 SG_ AerosolFaultState_03 : 5|2@1+ (1,0) [0|3] ""  MBMU,PC
 SG_ DoorState_03 : 7|1@1+ (1,0) [0|1] ""  MBMU,PC
 SG_ ControlBoxFanState_03 : 8|1@1+ (1,0) [0|1] ""  MBMU,PC
 SG_ ControlBoxTempHighWarning_03 : 9|1@1+ (1,0) [0|1] ""  MBMU,PC
 SG_ PowerSWState_03 : 10|1@1+ (1,0) [0|1] ""  MBMU,PC
 SG_ FaultClearCommand_03 : 11|1@1+ (1,0) [0|1] ""  MBMU,PC

BO_ 2332753732 S2A_DryContact__04: 8 SBMU
 SG_ FireFault_Level1_04 : 0|1@1+ (1,0) [0|1] ""  MBMU,PC
 SG_ FireFault_Level2_04 : 1|1@1+ (1,0) [0|1] ""  MBMU,PC
 SG_ TempState_04 : 2|1@1+ (1,0) [0|1] ""  MBMU,PC
 SG_ FogState_04 : 3|1@1+ (1,0) [0|1] ""  MBMU,PC
 SG_ AerosolState_04 : 4|1@1+ (1,0) [0|1] ""  MBMU,PC
 SG_ AerosolFaultState_04 : 5|2@1+ (1,0) [0|3] ""  MBMU,PC
 SG_ DoorState_04 : 7|1@1+ (1,0) [0|1] ""  MBMU,PC
 SG_ ControlBoxFanState_04 : 8|1@1+ (1,0) [0|1] ""  MBMU,PC
 SG_ ControlBoxTempHighWarning_04 : 9|1@1+ (1,0) [0|1] ""  MBMU,PC
 SG_ PowerSWState_04 : 10|1@1+ (1,0) [0|1] ""  MBMU,PC
 SG_ FaultClearCommand_04 : 11|1@1+ (1,0) [0|1] ""  MBMU,PC

BO_ 2332753733 S2A_DryContact__05: 8 SBMU
 SG_ FireFault_Level1_05 : 0|1@1+ (1,0) [0|1] ""  MBMU,PC
 SG_ FireFault_Level2_05 : 1|1@1+ (1,0) [0|1] ""  MBMU,PC
 SG_ TempState_05 : 2|1@1+ (1,0) [0|1] ""  MBMU,PC
 SG_ FogState_05 : 3|1@1+ (1,0) [0|1] ""  MBMU,PC
 SG_ AerosolState_05 : 4|1@1+ (1,0) [0|1] ""  MBMU,PC
 SG_ AerosolFaultState_05 : 5|2@1+ (1,0) [0|3] ""  MBMU,PC
 SG_ DoorState_05 : 7|1@1+ (1,0) [0|1] ""  MBMU,PC
 SG_ ControlBoxFanState_05 : 8|1@1+ (1,0) [0|1] ""  MBMU,PC
 SG_ ControlBoxTempHighWarning_05 : 9|1@1+ (1,0) [0|1] ""  MBMU,PC
 SG_ PowerSWState_05 : 10|1@1+ (1,0) [0|1] ""  MBMU,PC
 SG_ FaultClearCommand_05 : 11|1@1+ (1,0) [0|1] ""  MBMU,PC

BO_ 2332753734 S2A_DryContact__06: 8 SBMU
 SG_ FireFault_Level1_06 : 0|1@1+ (1,0) [0|1] ""  MBMU,PC
 SG_ FireFault_Level2_06 : 1|1@1+ (1,0) [0|1] ""  MBMU,PC
 SG_ TempState_06 : 2|1@1+ (1,0) [0|1] ""  MBMU,PC
 SG_ FogState_06 : 3|1@1+ (1,0) [0|1] ""  MBMU,PC
 SG_ AerosolState_06 : 4|1@1+ (1,0) [0|1] ""  MBMU,PC
 SG_ AerosolFaultState_06 : 5|2@1+ (1,0) [0|3] ""  MBMU,PC
 SG_ DoorState_06 : 7|1@1+ (1,0) [0|1] ""  MBMU,PC
 SG_ ControlBoxFanState_06 : 8|1@1+ (1,0) [0|1] ""  MBMU,PC
 SG_ ControlBoxTempHighWarning_06 : 9|1@1+ (1,0) [0|1] ""  MBMU,PC
 SG_ PowerSWState_06 : 10|1@1+ (1,0) [0|1] ""  MBMU,PC
 SG_ FaultClearCommand_06 : 11|1@1+ (1,0) [0|1] ""  MBMU,PC

BO_ 2332753735 S2A_DryContact__07: 8 SBMU
 SG_ FireFault_Level1_07 : 0|1@1+ (1,0) [0|1] ""  MBMU,PC
 SG_ FireFault_Level2_07 : 1|1@1+ (1,0) [0|1] ""  MBMU,PC
 SG_ TempState_07 : 2|1@1+ (1,0) [0|1] ""  MBMU,PC
 SG_ FogState_07 : 3|1@1+ (1,0) [0|1] ""  MBMU,PC
 SG_ AerosolState_07 : 4|1@1+ (1,0) [0|1] ""  MBMU,PC
 SG_ AerosolFaultState_07 : 5|2@1+ (1,0) [0|3] ""  MBMU,PC
 SG_ DoorState_07 : 7|1@1+ (1,0) [0|1] ""  MBMU,PC
 SG_ ControlBoxFanState_07 : 8|1@1+ (1,0) [0|1] ""  MBMU,PC
 SG_ ControlBoxTempHighWarning_07 : 9|1@1+ (1,0) [0|1] ""  MBMU,PC
 SG_ PowerSWState_07 : 10|1@1+ (1,0) [0|1] ""  MBMU,PC
 SG_ FaultClearCommand_07 : 11|1@1+ (1,0) [0|1] ""  MBMU,PC

BO_ 2332753736 S2A_DryContact__08: 8 SBMU
 SG_ FireFault_Level1_08 : 0|1@1+ (1,0) [0|1] ""  MBMU,PC
 SG_ FireFault_Level2_08 : 1|1@1+ (1,0) [0|1] ""  MBMU,PC
 SG_ TempState_08 : 2|1@1+ (1,0) [0|1] ""  MBMU,PC
 SG_ FogState_08 : 3|1@1+ (1,0) [0|1] ""  MBMU,PC
 SG_ AerosolState_08 : 4|1@1+ (1,0) [0|1] ""  MBMU,PC
 SG_ AerosolFaultState_08 : 5|2@1+ (1,0) [0|3] ""  MBMU,PC
 SG_ DoorState_08 : 7|1@1+ (1,0) [0|1] ""  MBMU,PC
 SG_ ControlBoxFanState_08 : 8|1@1+ (1,0) [0|1] ""  MBMU,PC
 SG_ ControlBoxTempHighWarning_08 : 9|1@1+ (1,0) [0|1] ""  MBMU,PC
 SG_ PowerSWState_08 : 10|1@1+ (1,0) [0|1] ""  MBMU,PC
 SG_ FaultClearCommand_08 : 11|1@1+ (1,0) [0|1] ""  MBMU,PC

BO_ 2332753737 S2A_DryContact__09: 8 SBMU
 SG_ FireFault_Level1_09 : 0|1@1+ (1,0) [0|1] ""  MBMU,PC
 SG_ FireFault_Level2_09 : 1|1@1+ (1,0) [0|1] ""  MBMU,PC
 SG_ TempState_09 : 2|1@1+ (1,0) [0|1] ""  MBMU,PC
 SG_ FogState_09 : 3|1@1+ (1,0) [0|1] ""  MBMU,PC
 SG_ AerosolState_09 : 4|1@1+ (1,0) [0|1] ""  MBMU,PC
 SG_ AerosolFaultState_09 : 5|2@1+ (1,0) [0|3] ""  MBMU,PC
 SG_ DoorState_09 : 7|1@1+ (1,0) [0|1] ""  MBMU,PC
 SG_ ControlBoxFanState_09 : 8|1@1+ (1,0) [0|1] ""  MBMU,PC
 SG_ ControlBoxTempHighWarning_09 : 9|1@1+ (1,0) [0|1] ""  MBMU,PC
 SG_ PowerSWState_09 : 10|1@1+ (1,0) [0|1] ""  MBMU,PC
 SG_ FaultClearCommand_09 : 11|1@1+ (1,0) [0|1] ""  MBMU,PC

BO_ 2332753738 S2A_DryContact__10: 8 SBMU
 SG_ FireFault_Level1_10 : 0|1@1+ (1,0) [0|1] ""  MBMU,PC
 SG_ FireFault_Level2_10 : 1|1@1+ (1,0) [0|1] ""  MBMU,PC
 SG_ TempState_10 : 2|1@1+ (1,0) [0|1] ""  MBMU,PC
 SG_ FogState_10 : 3|1@1+ (1,0) [0|1] ""  MBMU,PC
 SG_ AerosolState_10 : 4|1@1+ (1,0) [0|1] ""  MBMU,PC
 SG_ AerosolFaultState_10 : 5|2@1+ (1,0) [0|3] ""  MBMU,PC
 SG_ DoorState_10 : 7|1@1+ (1,0) [0|1] ""  MBMU,PC
 SG_ ControlBoxFanState_10 : 8|1@1+ (1,0) [0|1] ""  MBMU,PC
 SG_ ControlBoxTempHighWarning_10 : 9|1@1+ (1,0) [0|1] ""  MBMU,PC
 SG_ PowerSWState_10 : 10|1@1+ (1,0) [0|1] ""  MBMU,PC
 SG_ FaultClearCommand_10 : 11|1@1+ (1,0) [0|1] ""  MBMU,PC

BO_ 2332753739 S2A_DryContact__11: 8 SBMU
 SG_ FireFault_Level1_11 : 0|1@1+ (1,0) [0|1] ""  MBMU,PC
 SG_ FireFault_Level2_11 : 1|1@1+ (1,0) [0|1] ""  MBMU,PC
 SG_ TempState_11 : 2|1@1+ (1,0) [0|1] ""  MBMU,PC
 SG_ FogState_11 : 3|1@1+ (1,0) [0|1] ""  MBMU,PC
 SG_ AerosolState_11 : 4|1@1+ (1,0) [0|1] ""  MBMU,PC
 SG_ AerosolFaultState_11 : 5|2@1+ (1,0) [0|3] ""  MBMU,PC
 SG_ DoorState_11 : 7|1@1+ (1,0) [0|1] ""  MBMU,PC
 SG_ ControlBoxFanState_11 : 8|1@1+ (1,0) [0|1] ""  MBMU,PC
 SG_ ControlBoxTempHighWarning_11 : 9|1@1+ (1,0) [0|1] ""  MBMU,PC
 SG_ PowerSWState_11 : 10|1@1+ (1,0) [0|1] ""  MBMU,PC
 SG_ FaultClearCommand_11 : 11|1@1+ (1,0) [0|1] ""  MBMU,PC

BO_ 2332753740 S2A_DryContact__12: 8 SBMU
 SG_ FireFault_Level1_12 : 0|1@1+ (1,0) [0|1] ""  MBMU,PC
 SG_ FireFault_Level2_12 : 1|1@1+ (1,0) [0|1] ""  MBMU,PC
 SG_ TempState_12 : 2|1@1+ (1,0) [0|1] ""  MBMU,PC
 SG_ FogState_12 : 3|1@1+ (1,0) [0|1] ""  MBMU,PC
 SG_ AerosolState_12 : 4|1@1+ (1,0) [0|1] ""  MBMU,PC
 SG_ AerosolFaultState_12 : 5|2@1+ (1,0) [0|3] ""  MBMU,PC
 SG_ DoorState_12 : 7|1@1+ (1,0) [0|1] ""  MBMU,PC
 SG_ ControlBoxFanState_12 : 8|1@1+ (1,0) [0|1] ""  MBMU,PC
 SG_ ControlBoxTempHighWarning_12 : 9|1@1+ (1,0) [0|1] ""  MBMU,PC
 SG_ PowerSWState_12 : 10|1@1+ (1,0) [0|1] ""  MBMU,PC
 SG_ FaultClearCommand_12 : 11|1@1+ (1,0) [0|1] ""  MBMU,PC

BO_ 2332753741 S2A_DryContact__13: 8 SBMU
 SG_ FireFault_Level1_13 : 0|1@1+ (1,0) [0|1] ""  MBMU,PC
 SG_ FireFault_Level2_13 : 1|1@1+ (1,0) [0|1] ""  MBMU,PC
 SG_ TempState_13 : 2|1@1+ (1,0) [0|1] ""  MBMU,PC
 SG_ FogState_13 : 3|1@1+ (1,0) [0|1] ""  MBMU,PC
 SG_ AerosolState_13 : 4|1@1+ (1,0) [0|1] ""  MBMU,PC
 SG_ AerosolFaultState_13 : 5|2@1+ (1,0) [0|3] ""  MBMU,PC
 SG_ DoorState_13 : 7|1@1+ (1,0) [0|1] ""  MBMU,PC
 SG_ ControlBoxFanState_13 : 8|1@1+ (1,0) [0|1] ""  MBMU,PC
 SG_ ControlBoxTempHighWarning_13 : 9|1@1+ (1,0) [0|1] ""  MBMU,PC
 SG_ PowerSWState_13 : 10|1@1+ (1,0) [0|1] ""  MBMU,PC
 SG_ FaultClearCommand_13 : 11|1@1+ (1,0) [0|1] ""  MBMU,PC

BO_ 2332753742 S2A_DryContact__14: 8 SBMU
 SG_ FireFault_Level1_14 : 0|1@1+ (1,0) [0|1] ""  MBMU,PC
 SG_ FireFault_Level2_14 : 1|1@1+ (1,0) [0|1] ""  MBMU,PC
 SG_ TempState_14 : 2|1@1+ (1,0) [0|1] ""  MBMU,PC
 SG_ FogState_14 : 3|1@1+ (1,0) [0|1] ""  MBMU,PC
 SG_ AerosolState_14 : 4|1@1+ (1,0) [0|1] ""  MBMU,PC
 SG_ AerosolFaultState_14 : 5|2@1+ (1,0) [0|3] ""  MBMU,PC
 SG_ DoorState_14 : 7|1@1+ (1,0) [0|1] ""  MBMU,PC
 SG_ ControlBoxFanState_14 : 8|1@1+ (1,0) [0|1] ""  MBMU,PC
 SG_ ControlBoxTempHighWarning_14 : 9|1@1+ (1,0) [0|1] ""  MBMU,PC
 SG_ PowerSWState_14 : 10|1@1+ (1,0) [0|1] ""  MBMU,PC
 SG_ FaultClearCommand_14 : 11|1@1+ (1,0) [0|1] ""  MBMU,PC

BO_ 2332753743 S2A_DryContact__15: 8 SBMU
 SG_ FireFault_Level1_15 : 0|1@1+ (1,0) [0|1] ""  MBMU,PC
 SG_ FireFault_Level2_15 : 1|1@1+ (1,0) [0|1] ""  MBMU,PC
 SG_ TempState_15 : 2|1@1+ (1,0) [0|1] ""  MBMU,PC
 SG_ FogState_15 : 3|1@1+ (1,0) [0|1] ""  MBMU,PC
 SG_ AerosolState_15 : 4|1@1+ (1,0) [0|1] ""  MBMU,PC
 SG_ AerosolFaultState_15 : 5|2@1+ (1,0) [0|3] ""  MBMU,PC
 SG_ DoorState_15 : 7|1@1+ (1,0) [0|1] ""  MBMU,PC
 SG_ ControlBoxFanState_15 : 8|1@1+ (1,0) [0|1] ""  MBMU,PC
 SG_ ControlBoxTempHighWarning_15 : 9|1@1+ (1,0) [0|1] ""  MBMU,PC
 SG_ PowerSWState_15 : 10|1@1+ (1,0) [0|1] ""  MBMU,PC
 SG_ FaultClearCommand_15 : 11|1@1+ (1,0) [0|1] ""  MBMU,PC

BO_ 2332753744 S2A_DryContact__16: 8 SBMU
 SG_ FireFault_Level1_16 : 0|1@1+ (1,0) [0|1] ""  MBMU,PC
 SG_ FireFault_Level2_16 : 1|1@1+ (1,0) [0|1] ""  MBMU,PC
 SG_ TempState_16 : 2|1@1+ (1,0) [0|1] ""  MBMU,PC
 SG_ FogState_16 : 3|1@1+ (1,0) [0|1] ""  MBMU,PC
 SG_ AerosolState_16 : 4|1@1+ (1,0) [0|1] ""  MBMU,PC
 SG_ AerosolFaultState_16 : 5|2@1+ (1,0) [0|3] ""  MBMU,PC
 SG_ DoorState_16 : 7|1@1+ (1,0) [0|1] ""  MBMU,PC
 SG_ ControlBoxFanState_16 : 8|1@1+ (1,0) [0|1] ""  MBMU,PC
 SG_ ControlBoxTempHighWarning_16 : 9|1@1+ (1,0) [0|1] ""  MBMU,PC
 SG_ PowerSWState_16 : 10|1@1+ (1,0) [0|1] ""  MBMU,PC
 SG_ FaultClearCommand_16 : 11|1@1+ (1,0) [0|1] ""  MBMU,PC

BO_ 2332753745 S2A_DryContact__17: 8 SBMU
 SG_ FireFault_Level1_17 : 0|1@1+ (1,0) [0|1] ""  MBMU,PC
 SG_ FireFault_Level2_17 : 1|1@1+ (1,0) [0|1] ""  MBMU,PC
 SG_ TempState_17 : 2|1@1+ (1,0) [0|1] ""  MBMU,PC
 SG_ FogState_17 : 3|1@1+ (1,0) [0|1] ""  MBMU,PC
 SG_ AerosolState_17 : 4|1@1+ (1,0) [0|1] ""  MBMU,PC
 SG_ AerosolFaultState_17 : 5|2@1+ (1,0) [0|3] ""  MBMU,PC
 SG_ DoorState_17 : 7|1@1+ (1,0) [0|1] ""  MBMU,PC
 SG_ ControlBoxFanState_17 : 8|1@1+ (1,0) [0|1] ""  MBMU,PC
 SG_ ControlBoxTempHighWarning_17 : 9|1@1+ (1,0) [0|1] ""  MBMU,PC
 SG_ PowerSWState_17 : 10|1@1+ (1,0) [0|1] ""  MBMU,PC
 SG_ FaultClearCommand_17 : 11|1@1+ (1,0) [0|1] ""  MBMU,PC

BO_ 2332753746 S2A_DryContact__18: 8 SBMU
 SG_ FireFault_Level1_18 : 0|1@1+ (1,0) [0|1] ""  MBMU,PC
 SG_ FireFault_Level2_18 : 1|1@1+ (1,0) [0|1] ""  MBMU,PC
 SG_ TempState_18 : 2|1@1+ (1,0) [0|1] ""  MBMU,PC
 SG_ FogState_18 : 3|1@1+ (1,0) [0|1] ""  MBMU,PC
 SG_ AerosolState_18 : 4|1@1+ (1,0) [0|1] ""  MBMU,PC
 SG_ AerosolFaultState_18 : 5|2@1+ (1,0) [0|3] ""  MBMU,PC
 SG_ DoorState_18 : 7|1@1+ (1,0) [0|1] ""  MBMU,PC
 SG_ ControlBoxFanState_18 : 8|1@1+ (1,0) [0|1] ""  MBMU,PC
 SG_ ControlBoxTempHighWarning_18 : 9|1@1+ (1,0) [0|1] ""  MBMU,PC
 SG_ PowerSWState_18 : 10|1@1+ (1,0) [0|1] ""  MBMU,PC
 SG_ FaultClearCommand_18 : 11|1@1+ (1,0) [0|1] ""  MBMU,PC

BO_ 2332753747 S2A_DryContact__19: 8 SBMU
 SG_ FireFault_Level1_19 : 0|1@1+ (1,0) [0|1] ""  MBMU,PC
 SG_ FireFault_Level2_19 : 1|1@1+ (1,0) [0|1] ""  MBMU,PC
 SG_ TempState_19 : 2|1@1+ (1,0) [0|1] ""  MBMU,PC
 SG_ FogState_19 : 3|1@1+ (1,0) [0|1] ""  MBMU,PC
 SG_ AerosolState_19 : 4|1@1+ (1,0) [0|1] ""  MBMU,PC
 SG_ AerosolFaultState_19 : 5|2@1+ (1,0) [0|3] ""  MBMU,PC
 SG_ DoorState_19 : 7|1@1+ (1,0) [0|1] ""  MBMU,PC
 SG_ ControlBoxFanState_19 : 8|1@1+ (1,0) [0|1] ""  MBMU,PC
 SG_ ControlBoxTempHighWarning_19 : 9|1@1+ (1,0) [0|1] ""  MBMU,PC
 SG_ PowerSWState_19 : 10|1@1+ (1,0) [0|1] ""  MBMU,PC
 SG_ FaultClearCommand_19 : 11|1@1+ (1,0) [0|1] ""  MBMU,PC

CM_ SG_ 2332688195 B2T_ControlMode_03 "BMS请求设定模式";
CM_ SG_ 2332688195 TMS_RunState_03 "TMS运行状态";
CM_ SG_ 2332688195 TMS_CommuFault_03 "TMS通信丢失";
CM_ SG_ 2332688195 TMS_ModeConflict_03 "TMS运行模式与BMS控制指令冲突";
CM_ SG_ 2332688195 TMS_MakeBMSStop_03 "TMS致电柜停机故障";
CM_ SG_ 2332688195 TMS_HVRealyState_03 "TMS高压继电器状态";
CM_ SG_ 2332688195 TMS_FaultCode_03 "TMS故障码";
CM_ SG_ 2332688195 TMS_FaultLevel_03 "TMS故障码等级";
CM_ SG_ 2332688195 B2T_TmptSetPoint_03 "BMS请求设定温度";
CM_ SG_ 2332688195 TMS_OutWaterTemp_03 "TMS出水温度";
CM_ SG_ 2332688195 TMS_BackWaterTemp_03 "TMS回水温度";
CM_ SG_ 2332688195 TMS_EnvTemp_03 "TMS环境温度";
CM_ SG_ 2332688195 TMS_RequestPower_03 "TMS需求功率";
CM_ SG_ 2332688195 STMS_ThrmStopReason_03 "热管理停机原因";
CM_ SG_ 2332688196 B2T_ControlMode_04 "BMS请求设定模式";
CM_ SG_ 2332688196 TMS_RunState_04 "TMS运行状态";
CM_ SG_ 2332688196 TMS_CommuFault_04 "TMS通信丢失";
CM_ SG_ 2332688196 TMS_ModeConflict_04 "TMS运行模式与BMS控制指令冲突";
CM_ SG_ 2332688196 TMS_MakeBMSStop_04 "TMS致电柜停机故障";
CM_ SG_ 2332688196 TMS_HVRealyState_04 "TMS高压继电器状态";
CM_ SG_ 2332688196 TMS_FaultCode_04 "TMS故障码";
CM_ SG_ 2332688196 TMS_FaultLevel_04 "TMS故障码等级";
CM_ SG_ 2332688196 B2T_TmptSetPoint_04 "BMS请求设定温度";
CM_ SG_ 2332688196 TMS_OutWaterTemp_04 "TMS出水温度";
CM_ SG_ 2332688196 TMS_BackWaterTemp_04 "TMS回水温度";
CM_ SG_ 2332688196 TMS_EnvTemp_04 "TMS环境温度";
CM_ SG_ 2332688196 TMS_RequestPower_04 "TMS需求功率";
CM_ SG_ 2332688196 STMS_ThrmStopReason_04 "热管理停机原因";
CM_ SG_ 2332688197 B2T_ControlMode_05 "BMS请求设定模式";
CM_ SG_ 2332688197 TMS_RunState_05 "TMS运行状态";
CM_ SG_ 2332688197 TMS_CommuFault_05 "TMS通信丢失";
CM_ SG_ 2332688197 TMS_ModeConflict_05 "TMS运行模式与BMS控制指令冲突";
CM_ SG_ 2332688197 TMS_MakeBMSStop_05 "TMS致电柜停机故障";
CM_ SG_ 2332688197 TMS_HVRealyState_05 "TMS高压继电器状态";
CM_ SG_ 2332688197 TMS_FaultCode_05 "TMS故障码";
CM_ SG_ 2332688197 TMS_FaultLevel_05 "TMS故障码等级";
CM_ SG_ 2332688197 B2T_TmptSetPoint_05 "BMS请求设定温度";
CM_ SG_ 2332688197 TMS_OutWaterTemp_05 "TMS出水温度";
CM_ SG_ 2332688197 TMS_BackWaterTemp_05 "TMS回水温度";
CM_ SG_ 2332688197 TMS_EnvTemp_05 "TMS环境温度";
CM_ SG_ 2332688197 TMS_RequestPower_05 "TMS需求功率";
CM_ SG_ 2332688197 STMS_ThrmStopReason_05 "热管理停机原因";
CM_ SG_ 2332688198 B2T_ControlMode_06 "BMS请求设定模式";
CM_ SG_ 2332688198 TMS_RunState_06 "TMS运行状态";
CM_ SG_ 2332688198 TMS_CommuFault_06 "TMS通信丢失";
CM_ SG_ 2332688198 TMS_ModeConflict_06 "TMS运行模式与BMS控制指令冲突";
CM_ SG_ 2332688198 TMS_MakeBMSStop_06 "TMS致电柜停机故障";
CM_ SG_ 2332688198 TMS_HVRealyState_06 "TMS高压继电器状态";
CM_ SG_ 2332688198 TMS_FaultCode_06 "TMS故障码";
CM_ SG_ 2332688198 TMS_FaultLevel_06 "TMS故障码等级";
CM_ SG_ 2332688198 B2T_TmptSetPoint_06 "BMS请求设定温度";
CM_ SG_ 2332688198 TMS_OutWaterTemp_06 "TMS出水温度";
CM_ SG_ 2332688198 TMS_BackWaterTemp_06 "TMS回水温度";
CM_ SG_ 2332688198 TMS_EnvTemp_06 "TMS环境温度";
CM_ SG_ 2332688198 TMS_RequestPower_06 "TMS需求功率";
CM_ SG_ 2332688198 STMS_ThrmStopReason_06 "热管理停机原因";
CM_ SG_ 2332688199 B2T_ControlMode_07 "BMS请求设定模式";
CM_ SG_ 2332688199 TMS_RunState_07 "TMS运行状态";
CM_ SG_ 2332688199 TMS_CommuFault_07 "TMS通信丢失";
CM_ SG_ 2332688199 TMS_ModeConflict_07 "TMS运行模式与BMS控制指令冲突";
CM_ SG_ 2332688199 TMS_MakeBMSStop_07 "TMS致电柜停机故障";
CM_ SG_ 2332688199 TMS_HVRealyState_07 "TMS高压继电器状态";
CM_ SG_ 2332688199 TMS_FaultCode_07 "TMS故障码";
CM_ SG_ 2332688199 TMS_FaultLevel_07 "TMS故障码等级";
CM_ SG_ 2332688199 B2T_TmptSetPoint_07 "BMS请求设定温度";
CM_ SG_ 2332688199 TMS_OutWaterTemp_07 "TMS出水温度";
CM_ SG_ 2332688199 TMS_BackWaterTemp_07 "TMS回水温度";
CM_ SG_ 2332688199 TMS_EnvTemp_07 "TMS环境温度";
CM_ SG_ 2332688199 TMS_RequestPower_07 "TMS需求功率";
CM_ SG_ 2332688199 STMS_ThrmStopReason_07 "热管理停机原因";
CM_ SG_ 2332688200 B2T_ControlMode_08 "BMS请求设定模式";
CM_ SG_ 2332688200 TMS_RunState_08 "TMS运行状态";
CM_ SG_ 2332688200 TMS_CommuFault_08 "TMS通信丢失";
CM_ SG_ 2332688200 TMS_ModeConflict_08 "TMS运行模式与BMS控制指令冲突";
CM_ SG_ 2332688200 TMS_MakeBMSStop_08 "TMS致电柜停机故障";
CM_ SG_ 2332688200 TMS_HVRealyState_08 "TMS高压继电器状态";
CM_ SG_ 2332688200 TMS_FaultCode_08 "TMS故障码";
CM_ SG_ 2332688200 TMS_FaultLevel_08 "TMS故障码等级";
CM_ SG_ 2332688200 B2T_TmptSetPoint_08 "BMS请求设定温度";
CM_ SG_ 2332688200 TMS_OutWaterTemp_08 "TMS出水温度";
CM_ SG_ 2332688200 TMS_BackWaterTemp_08 "TMS回水温度";
CM_ SG_ 2332688200 TMS_EnvTemp_08 "TMS环境温度";
CM_ SG_ 2332688200 TMS_RequestPower_08 "TMS需求功率";
CM_ SG_ 2332688200 STMS_ThrmStopReason_08 "热管理停机原因";
CM_ SG_ 2332688201 B2T_ControlMode_09 "BMS请求设定模式";
CM_ SG_ 2332688201 TMS_RunState_09 "TMS运行状态";
CM_ SG_ 2332688201 TMS_CommuFault_09 "TMS通信丢失";
CM_ SG_ 2332688201 TMS_ModeConflict_09 "TMS运行模式与BMS控制指令冲突";
CM_ SG_ 2332688201 TMS_MakeBMSStop_09 "TMS致电柜停机故障";
CM_ SG_ 2332688201 TMS_HVRealyState_09 "TMS高压继电器状态";
CM_ SG_ 2332688201 TMS_FaultCode_09 "TMS故障码";
CM_ SG_ 2332688201 TMS_FaultLevel_09 "TMS故障码等级";
CM_ SG_ 2332688201 B2T_TmptSetPoint_09 "BMS请求设定温度";
CM_ SG_ 2332688201 TMS_OutWaterTemp_09 "TMS出水温度";
CM_ SG_ 2332688201 TMS_BackWaterTemp_09 "TMS回水温度";
CM_ SG_ 2332688201 TMS_EnvTemp_09 "TMS环境温度";
CM_ SG_ 2332688201 TMS_RequestPower_09 "TMS需求功率";
CM_ SG_ 2332688201 STMS_ThrmStopReason_09 "热管理停机原因";
CM_ SG_ 2332688202 B2T_ControlMode_10 "BMS请求设定模式";
CM_ SG_ 2332688202 TMS_RunState_10 "TMS运行状态";
CM_ SG_ 2332688202 TMS_CommuFault_10 "TMS通信丢失";
CM_ SG_ 2332688202 TMS_ModeConflict_10 "TMS运行模式与BMS控制指令冲突";
CM_ SG_ 2332688202 TMS_MakeBMSStop_10 "TMS致电柜停机故障";
CM_ SG_ 2332688202 TMS_HVRealyState_10 "TMS高压继电器状态";
CM_ SG_ 2332688202 TMS_FaultCode_10 "TMS故障码";
CM_ SG_ 2332688202 TMS_FaultLevel_10 "TMS故障码等级";
CM_ SG_ 2332688202 B2T_TmptSetPoint_10 "BMS请求设定温度";
CM_ SG_ 2332688202 TMS_OutWaterTemp_10 "TMS出水温度";
CM_ SG_ 2332688202 TMS_BackWaterTemp_10 "TMS回水温度";
CM_ SG_ 2332688202 TMS_EnvTemp_10 "TMS环境温度";
CM_ SG_ 2332688202 TMS_RequestPower_10 "TMS需求功率";
CM_ SG_ 2332688202 STMS_ThrmStopReason_10 "热管理停机原因";
CM_ SG_ 2332688203 B2T_ControlMode_11 "BMS请求设定模式";
CM_ SG_ 2332688203 TMS_RunState_11 "TMS运行状态";
CM_ SG_ 2332688203 TMS_CommuFault_11 "TMS通信丢失";
CM_ SG_ 2332688203 TMS_ModeConflict_11 "TMS运行模式与BMS控制指令冲突";
CM_ SG_ 2332688203 TMS_MakeBMSStop_11 "TMS致电柜停机故障";
CM_ SG_ 2332688203 TMS_HVRealyState_11 "TMS高压继电器状态";
CM_ SG_ 2332688203 TMS_FaultCode_11 "TMS故障码";
CM_ SG_ 2332688203 TMS_FaultLevel_11 "TMS故障码等级";
CM_ SG_ 2332688203 B2T_TmptSetPoint_11 "BMS请求设定温度";
CM_ SG_ 2332688203 TMS_OutWaterTemp_11 "TMS出水温度";
CM_ SG_ 2332688203 TMS_BackWaterTemp_11 "TMS回水温度";
CM_ SG_ 2332688203 TMS_EnvTemp_11 "TMS环境温度";
CM_ SG_ 2332688203 TMS_RequestPower_11 "TMS需求功率";
CM_ SG_ 2332688203 STMS_ThrmStopReason_11 "热管理停机原因";
CM_ SG_ 2332688204 B2T_ControlMode_12 "BMS请求设定模式";
CM_ SG_ 2332688204 TMS_RunState_12 "TMS运行状态";
CM_ SG_ 2332688204 TMS_CommuFault_12 "TMS通信丢失";
CM_ SG_ 2332688204 TMS_ModeConflict_12 "TMS运行模式与BMS控制指令冲突";
CM_ SG_ 2332688204 TMS_MakeBMSStop_12 "TMS致电柜停机故障";
CM_ SG_ 2332688204 TMS_HVRealyState_12 "TMS高压继电器状态";
CM_ SG_ 2332688204 TMS_FaultCode_12 "TMS故障码";
CM_ SG_ 2332688204 TMS_FaultLevel_12 "TMS故障码等级";
CM_ SG_ 2332688204 B2T_TmptSetPoint_12 "BMS请求设定温度";
CM_ SG_ 2332688204 TMS_OutWaterTemp_12 "TMS出水温度";
CM_ SG_ 2332688204 TMS_BackWaterTemp_12 "TMS回水温度";
CM_ SG_ 2332688204 TMS_EnvTemp_12 "TMS环境温度";
CM_ SG_ 2332688204 TMS_RequestPower_12 "TMS需求功率";
CM_ SG_ 2332688204 STMS_ThrmStopReason_12 "热管理停机原因";
CM_ SG_ 2332688205 B2T_ControlMode_13 "BMS请求设定模式";
CM_ SG_ 2332688205 TMS_RunState_13 "TMS运行状态";
CM_ SG_ 2332688205 TMS_CommuFault_13 "TMS通信丢失";
CM_ SG_ 2332688205 TMS_ModeConflict_13 "TMS运行模式与BMS控制指令冲突";
CM_ SG_ 2332688205 TMS_MakeBMSStop_13 "TMS致电柜停机故障";
CM_ SG_ 2332688205 TMS_HVRealyState_13 "TMS高压继电器状态";
CM_ SG_ 2332688205 TMS_FaultCode_13 "TMS故障码";
CM_ SG_ 2332688205 TMS_FaultLevel_13 "TMS故障码等级";
CM_ SG_ 2332688205 B2T_TmptSetPoint_13 "BMS请求设定温度";
CM_ SG_ 2332688205 TMS_OutWaterTemp_13 "TMS出水温度";
CM_ SG_ 2332688205 TMS_BackWaterTemp_13 "TMS回水温度";
CM_ SG_ 2332688205 TMS_EnvTemp_13 "TMS环境温度";
CM_ SG_ 2332688205 TMS_RequestPower_13 "TMS需求功率";
CM_ SG_ 2332688205 STMS_ThrmStopReason_13 "热管理停机原因";
CM_ SG_ 2332688206 B2T_ControlMode_14 "BMS请求设定模式";
CM_ SG_ 2332688206 TMS_RunState_14 "TMS运行状态";
CM_ SG_ 2332688206 TMS_CommuFault_14 "TMS通信丢失";
CM_ SG_ 2332688206 TMS_ModeConflict_14 "TMS运行模式与BMS控制指令冲突";
CM_ SG_ 2332688206 TMS_MakeBMSStop_14 "TMS致电柜停机故障";
CM_ SG_ 2332688206 TMS_HVRealyState_14 "TMS高压继电器状态";
CM_ SG_ 2332688206 TMS_FaultCode_14 "TMS故障码";
CM_ SG_ 2332688206 TMS_FaultLevel_14 "TMS故障码等级";
CM_ SG_ 2332688206 B2T_TmptSetPoint_14 "BMS请求设定温度";
CM_ SG_ 2332688206 TMS_OutWaterTemp_14 "TMS出水温度";
CM_ SG_ 2332688206 TMS_BackWaterTemp_14 "TMS回水温度";
CM_ SG_ 2332688206 TMS_EnvTemp_14 "TMS环境温度";
CM_ SG_ 2332688206 TMS_RequestPower_14 "TMS需求功率";
CM_ SG_ 2332688206 STMS_ThrmStopReason_14 "热管理停机原因";
CM_ SG_ 2332688207 B2T_ControlMode_15 "BMS请求设定模式";
CM_ SG_ 2332688207 TMS_RunState_15 "TMS运行状态";
CM_ SG_ 2332688207 TMS_CommuFault_15 "TMS通信丢失";
CM_ SG_ 2332688207 TMS_ModeConflict_15 "TMS运行模式与BMS控制指令冲突";
CM_ SG_ 2332688207 TMS_MakeBMSStop_15 "TMS致电柜停机故障";
CM_ SG_ 2332688207 TMS_HVRealyState_15 "TMS高压继电器状态";
CM_ SG_ 2332688207 TMS_FaultCode_15 "TMS故障码";
CM_ SG_ 2332688207 TMS_FaultLevel_15 "TMS故障码等级";
CM_ SG_ 2332688207 B2T_TmptSetPoint_15 "BMS请求设定温度";
CM_ SG_ 2332688207 TMS_OutWaterTemp_15 "TMS出水温度";
CM_ SG_ 2332688207 TMS_BackWaterTemp_15 "TMS回水温度";
CM_ SG_ 2332688207 TMS_EnvTemp_15 "TMS环境温度";
CM_ SG_ 2332688207 TMS_RequestPower_15 "TMS需求功率";
CM_ SG_ 2332688207 STMS_ThrmStopReason_15 "热管理停机原因";
CM_ SG_ 2332688208 B2T_ControlMode_16 "BMS请求设定模式";
CM_ SG_ 2332688208 TMS_RunState_16 "TMS运行状态";
CM_ SG_ 2332688208 TMS_CommuFault_16 "TMS通信丢失";
CM_ SG_ 2332688208 TMS_ModeConflict_16 "TMS运行模式与BMS控制指令冲突";
CM_ SG_ 2332688208 TMS_MakeBMSStop_16 "TMS致电柜停机故障";
CM_ SG_ 2332688208 TMS_HVRealyState_16 "TMS高压继电器状态";
CM_ SG_ 2332688208 TMS_FaultCode_16 "TMS故障码";
CM_ SG_ 2332688208 TMS_FaultLevel_16 "TMS故障码等级";
CM_ SG_ 2332688208 B2T_TmptSetPoint_16 "BMS请求设定温度";
CM_ SG_ 2332688208 TMS_OutWaterTemp_16 "TMS出水温度";
CM_ SG_ 2332688208 TMS_BackWaterTemp_16 "TMS回水温度";
CM_ SG_ 2332688208 TMS_EnvTemp_16 "TMS环境温度";
CM_ SG_ 2332688208 TMS_RequestPower_16 "TMS需求功率";
CM_ SG_ 2332688208 STMS_ThrmStopReason_16 "热管理停机原因";
CM_ SG_ 2332688209 B2T_ControlMode_17 "BMS请求设定模式";
CM_ SG_ 2332688209 TMS_RunState_17 "TMS运行状态";
CM_ SG_ 2332688209 TMS_CommuFault_17 "TMS通信丢失";
CM_ SG_ 2332688209 TMS_ModeConflict_17 "TMS运行模式与BMS控制指令冲突";
CM_ SG_ 2332688209 TMS_MakeBMSStop_17 "TMS致电柜停机故障";
CM_ SG_ 2332688209 TMS_HVRealyState_17 "TMS高压继电器状态";
CM_ SG_ 2332688209 TMS_FaultCode_17 "TMS故障码";
CM_ SG_ 2332688209 TMS_FaultLevel_17 "TMS故障码等级";
CM_ SG_ 2332688209 B2T_TmptSetPoint_17 "BMS请求设定温度";
CM_ SG_ 2332688209 TMS_OutWaterTemp_17 "TMS出水温度";
CM_ SG_ 2332688209 TMS_BackWaterTemp_17 "TMS回水温度";
CM_ SG_ 2332688209 TMS_EnvTemp_17 "TMS环境温度";
CM_ SG_ 2332688209 TMS_RequestPower_17 "TMS需求功率";
CM_ SG_ 2332688209 STMS_ThrmStopReason_17 "热管理停机原因";
CM_ SG_ 2332688210 B2T_ControlMode_18 "BMS请求设定模式";
CM_ SG_ 2332688210 TMS_RunState_18 "TMS运行状态";
CM_ SG_ 2332688210 TMS_CommuFault_18 "TMS通信丢失";
CM_ SG_ 2332688210 TMS_ModeConflict_18 "TMS运行模式与BMS控制指令冲突";
CM_ SG_ 2332688210 TMS_MakeBMSStop_18 "TMS致电柜停机故障";
CM_ SG_ 2332688210 TMS_HVRealyState_18 "TMS高压继电器状态";
CM_ SG_ 2332688210 TMS_FaultCode_18 "TMS故障码";
CM_ SG_ 2332688210 TMS_FaultLevel_18 "TMS故障码等级";
CM_ SG_ 2332688210 B2T_TmptSetPoint_18 "BMS请求设定温度";
CM_ SG_ 2332688210 TMS_OutWaterTemp_18 "TMS出水温度";
CM_ SG_ 2332688210 TMS_BackWaterTemp_18 "TMS回水温度";
CM_ SG_ 2332688210 TMS_EnvTemp_18 "TMS环境温度";
CM_ SG_ 2332688210 TMS_RequestPower_18 "TMS需求功率";
CM_ SG_ 2332688210 STMS_ThrmStopReason_18 "热管理停机原因";
CM_ SG_ 2332688211 B2T_ControlMode_19 "BMS请求设定模式";
CM_ SG_ 2332688211 TMS_RunState_19 "TMS运行状态";
CM_ SG_ 2332688211 TMS_CommuFault_19 "TMS通信丢失";
CM_ SG_ 2332688211 TMS_ModeConflict_19 "TMS运行模式与BMS控制指令冲突";
CM_ SG_ 2332688211 TMS_MakeBMSStop_19 "TMS致电柜停机故障";
CM_ SG_ 2332688211 TMS_HVRealyState_19 "TMS高压继电器状态";
CM_ SG_ 2332688211 TMS_FaultCode_19 "TMS故障码";
CM_ SG_ 2332688211 TMS_FaultLevel_19 "TMS故障码等级";
CM_ SG_ 2332688211 B2T_TmptSetPoint_19 "BMS请求设定温度";
CM_ SG_ 2332688211 TMS_OutWaterTemp_19 "TMS出水温度";
CM_ SG_ 2332688211 TMS_BackWaterTemp_19 "TMS回水温度";
CM_ SG_ 2332688211 TMS_EnvTemp_19 "TMS环境温度";
CM_ SG_ 2332688211 TMS_RequestPower_19 "TMS需求功率";
CM_ SG_ 2332688211 STMS_ThrmStopReason_19 "热管理停机原因";
CM_ SG_ 2332688212 B2T_ControlMode_20 "BMS请求设定模式";
CM_ SG_ 2332688212 TMS_RunState_20 "TMS运行状态";
CM_ SG_ 2332688212 TMS_CommuFault_20 "TMS通信丢失";
CM_ SG_ 2332688212 TMS_ModeConflict_20 "TMS运行模式与BMS控制指令冲突";
CM_ SG_ 2332688212 TMS_MakeBMSStop_20 "TMS致电柜停机故障";
CM_ SG_ 2332688212 TMS_HVRealyState_20 "TMS高压继电器状态";
CM_ SG_ 2332688212 TMS_FaultCode_20 "TMS故障码";
CM_ SG_ 2332688212 TMS_FaultLevel_20 "TMS故障码等级";
CM_ SG_ 2332688212 B2T_TmptSetPoint_20 "BMS请求设定温度";
CM_ SG_ 2332688212 TMS_OutWaterTemp_20 "TMS出水温度";
CM_ SG_ 2332688212 TMS_BackWaterTemp_20 "TMS回水温度";
CM_ SG_ 2332688212 TMS_EnvTemp_20 "TMS环境温度";
CM_ SG_ 2332688212 TMS_RequestPower_20 "TMS需求功率";
CM_ SG_ 2332688212 STMS_ThrmStopReason_20 "热管理停机原因";
CM_ SG_ 2332688213 B2T_ControlMode_21 "BMS请求设定模式";
CM_ SG_ 2332688213 TMS_RunState_21 "TMS运行状态";
CM_ SG_ 2332688213 TMS_CommuFault_21 "TMS通信丢失";
CM_ SG_ 2332688213 TMS_ModeConflict_21 "TMS运行模式与BMS控制指令冲突";
CM_ SG_ 2332688213 TMS_MakeBMSStop_21 "TMS致电柜停机故障";
CM_ SG_ 2332688213 TMS_HVRealyState_21 "TMS高压继电器状态";
CM_ SG_ 2332688213 TMS_FaultCode_21 "TMS故障码";
CM_ SG_ 2332688213 TMS_FaultLevel_21 "TMS故障码等级";
CM_ SG_ 2332688213 B2T_TmptSetPoint_21 "BMS请求设定温度";
CM_ SG_ 2332688213 TMS_OutWaterTemp_21 "TMS出水温度";
CM_ SG_ 2332688213 TMS_BackWaterTemp_21 "TMS回水温度";
CM_ SG_ 2332688213 TMS_EnvTemp_21 "TMS环境温度";
CM_ SG_ 2332688213 TMS_RequestPower_21 "TMS需求功率";
CM_ SG_ 2332688213 STMS_ThrmStopReason_21 "热管理停机原因";
CM_ SG_ 2332688214 B2T_ControlMode_22 "BMS请求设定模式";
CM_ SG_ 2332688214 TMS_RunState_22 "TMS运行状态";
CM_ SG_ 2332688214 TMS_CommuFault_22 "TMS通信丢失";
CM_ SG_ 2332688214 TMS_ModeConflict_22 "TMS运行模式与BMS控制指令冲突";
CM_ SG_ 2332688214 TMS_MakeBMSStop_22 "TMS致电柜停机故障";
CM_ SG_ 2332688214 TMS_HVRealyState_22 "TMS高压继电器状态";
CM_ SG_ 2332688214 TMS_FaultCode_22 "TMS故障码";
CM_ SG_ 2332688214 TMS_FaultLevel_22 "TMS故障码等级";
CM_ SG_ 2332688214 B2T_TmptSetPoint_22 "BMS请求设定温度";
CM_ SG_ 2332688214 TMS_OutWaterTemp_22 "TMS出水温度";
CM_ SG_ 2332688214 TMS_BackWaterTemp_22 "TMS回水温度";
CM_ SG_ 2332688214 TMS_EnvTemp_22 "TMS环境温度";
CM_ SG_ 2332688214 TMS_RequestPower_22 "TMS需求功率";
CM_ SG_ 2332688214 STMS_ThrmStopReason_22 "热管理停机原因";
CM_ SG_ 2332688215 B2T_ControlMode_23 "BMS请求设定模式";
CM_ SG_ 2332688215 TMS_RunState_23 "TMS运行状态";
CM_ SG_ 2332688215 TMS_CommuFault_23 "TMS通信丢失";
CM_ SG_ 2332688215 TMS_ModeConflict_23 "TMS运行模式与BMS控制指令冲突";
CM_ SG_ 2332688215 TMS_MakeBMSStop_23 "TMS致电柜停机故障";
CM_ SG_ 2332688215 TMS_HVRealyState_23 "TMS高压继电器状态";
CM_ SG_ 2332688215 TMS_FaultCode_23 "TMS故障码";
CM_ SG_ 2332688215 TMS_FaultLevel_23 "TMS故障码等级";
CM_ SG_ 2332688215 B2T_TmptSetPoint_23 "BMS请求设定温度";
CM_ SG_ 2332688215 TMS_OutWaterTemp_23 "TMS出水温度";
CM_ SG_ 2332688215 TMS_BackWaterTemp_23 "TMS回水温度";
CM_ SG_ 2332688215 TMS_EnvTemp_23 "TMS环境温度";
CM_ SG_ 2332688215 TMS_RequestPower_23 "TMS需求功率";
CM_ SG_ 2332688215 STMS_ThrmStopReason_23 "热管理停机原因";
CM_ SG_ 2332688216 B2T_ControlMode_24 "BMS请求设定模式";
CM_ SG_ 2332688216 TMS_RunState_24 "TMS运行状态";
CM_ SG_ 2332688216 TMS_CommuFault_24 "TMS通信丢失";
CM_ SG_ 2332688216 TMS_ModeConflict_24 "TMS运行模式与BMS控制指令冲突";
CM_ SG_ 2332688216 TMS_MakeBMSStop_24 "TMS致电柜停机故障";
CM_ SG_ 2332688216 TMS_HVRealyState_24 "TMS高压继电器状态";
CM_ SG_ 2332688216 TMS_FaultCode_24 "TMS故障码";
CM_ SG_ 2332688216 TMS_FaultLevel_24 "TMS故障码等级";
CM_ SG_ 2332688216 B2T_TmptSetPoint_24 "BMS请求设定温度";
CM_ SG_ 2332688216 TMS_OutWaterTemp_24 "TMS出水温度";
CM_ SG_ 2332688216 TMS_BackWaterTemp_24 "TMS回水温度";
CM_ SG_ 2332688216 TMS_EnvTemp_24 "TMS环境温度";
CM_ SG_ 2332688216 TMS_RequestPower_24 "TMS需求功率";
CM_ SG_ 2332688216 STMS_ThrmStopReason_24 "热管理停机原因";
CM_ SG_ 2332688217 B2T_ControlMode_25 "BMS请求设定模式";
CM_ SG_ 2332688217 TMS_RunState_25 "TMS运行状态";
CM_ SG_ 2332688217 TMS_CommuFault_25 "TMS通信丢失";
CM_ SG_ 2332688217 TMS_ModeConflict_25 "TMS运行模式与BMS控制指令冲突";
CM_ SG_ 2332688217 TMS_MakeBMSStop_25 "TMS致电柜停机故障";
CM_ SG_ 2332688217 TMS_HVRealyState_25 "TMS高压继电器状态";
CM_ SG_ 2332688217 TMS_FaultCode_25 "TMS故障码";
CM_ SG_ 2332688217 TMS_FaultLevel_25 "TMS故障码等级";
CM_ SG_ 2332688217 B2T_TmptSetPoint_25 "BMS请求设定温度";
CM_ SG_ 2332688217 TMS_OutWaterTemp_25 "TMS出水温度";
CM_ SG_ 2332688217 TMS_BackWaterTemp_25 "TMS回水温度";
CM_ SG_ 2332688217 TMS_EnvTemp_25 "TMS环境温度";
CM_ SG_ 2332688217 TMS_RequestPower_25 "TMS需求功率";
CM_ SG_ 2332688217 STMS_ThrmStopReason_25 "热管理停机原因";
CM_ SG_ 2332688218 B2T_ControlMode_26 "BMS请求设定模式";
CM_ SG_ 2332688218 TMS_RunState_26 "TMS运行状态";
CM_ SG_ 2332688218 TMS_CommuFault_26 "TMS通信丢失";
CM_ SG_ 2332688218 TMS_ModeConflict_26 "TMS运行模式与BMS控制指令冲突";
CM_ SG_ 2332688218 TMS_MakeBMSStop_26 "TMS致电柜停机故障";
CM_ SG_ 2332688218 TMS_HVRealyState_26 "TMS高压继电器状态";
CM_ SG_ 2332688218 TMS_FaultCode_26 "TMS故障码";
CM_ SG_ 2332688218 TMS_FaultLevel_26 "TMS故障码等级";
CM_ SG_ 2332688218 B2T_TmptSetPoint_26 "BMS请求设定温度";
CM_ SG_ 2332688218 TMS_OutWaterTemp_26 "TMS出水温度";
CM_ SG_ 2332688218 TMS_BackWaterTemp_26 "TMS回水温度";
CM_ SG_ 2332688218 TMS_EnvTemp_26 "TMS环境温度";
CM_ SG_ 2332688218 TMS_RequestPower_26 "TMS需求功率";
CM_ SG_ 2332688218 STMS_ThrmStopReason_26 "热管理停机原因";
CM_ SG_ 2332688219 B2T_ControlMode_27 "BMS请求设定模式";
CM_ SG_ 2332688219 TMS_RunState_27 "TMS运行状态";
CM_ SG_ 2332688219 TMS_CommuFault_27 "TMS通信丢失";
CM_ SG_ 2332688219 TMS_ModeConflict_27 "TMS运行模式与BMS控制指令冲突";
CM_ SG_ 2332688219 TMS_MakeBMSStop_27 "TMS致电柜停机故障";
CM_ SG_ 2332688219 TMS_HVRealyState_27 "TMS高压继电器状态";
CM_ SG_ 2332688219 TMS_FaultCode_27 "TMS故障码";
CM_ SG_ 2332688219 TMS_FaultLevel_27 "TMS故障码等级";
CM_ SG_ 2332688219 B2T_TmptSetPoint_27 "BMS请求设定温度";
CM_ SG_ 2332688219 TMS_OutWaterTemp_27 "TMS出水温度";
CM_ SG_ 2332688219 TMS_BackWaterTemp_27 "TMS回水温度";
CM_ SG_ 2332688219 TMS_EnvTemp_27 "TMS环境温度";
CM_ SG_ 2332688219 TMS_RequestPower_27 "TMS需求功率";
CM_ SG_ 2332688219 STMS_ThrmStopReason_27 "热管理停机原因";
CM_ SG_ 2332688220 B2T_ControlMode_28 "BMS请求设定模式";
CM_ SG_ 2332688220 TMS_RunState_28 "TMS运行状态";
CM_ SG_ 2332688220 TMS_CommuFault_28 "TMS通信丢失";
CM_ SG_ 2332688220 TMS_ModeConflict_28 "TMS运行模式与BMS控制指令冲突";
CM_ SG_ 2332688220 TMS_MakeBMSStop_28 "TMS致电柜停机故障";
CM_ SG_ 2332688220 TMS_HVRealyState_28 "TMS高压继电器状态";
CM_ SG_ 2332688220 TMS_FaultCode_28 "TMS故障码";
CM_ SG_ 2332688220 TMS_FaultLevel_28 "TMS故障码等级";
CM_ SG_ 2332688220 B2T_TmptSetPoint_28 "BMS请求设定温度";
CM_ SG_ 2332688220 TMS_OutWaterTemp_28 "TMS出水温度";
CM_ SG_ 2332688220 TMS_BackWaterTemp_28 "TMS回水温度";
CM_ SG_ 2332688220 TMS_EnvTemp_28 "TMS环境温度";
CM_ SG_ 2332688220 TMS_RequestPower_28 "TMS需求功率";
CM_ SG_ 2332688220 STMS_ThrmStopReason_28 "热管理停机原因";
CM_ SG_ 2332688221 B2T_ControlMode_29 "BMS请求设定模式";
CM_ SG_ 2332688221 TMS_RunState_29 "TMS运行状态";
CM_ SG_ 2332688221 TMS_CommuFault_29 "TMS通信丢失";
CM_ SG_ 2332688221 TMS_ModeConflict_29 "TMS运行模式与BMS控制指令冲突";
CM_ SG_ 2332688221 TMS_MakeBMSStop_29 "TMS致电柜停机故障";
CM_ SG_ 2332688221 TMS_HVRealyState_29 "TMS高压继电器状态";
CM_ SG_ 2332688221 TMS_FaultCode_29 "TMS故障码";
CM_ SG_ 2332688221 TMS_FaultLevel_29 "TMS故障码等级";
CM_ SG_ 2332688221 B2T_TmptSetPoint_29 "BMS请求设定温度";
CM_ SG_ 2332688221 TMS_OutWaterTemp_29 "TMS出水温度";
CM_ SG_ 2332688221 TMS_BackWaterTemp_29 "TMS回水温度";
CM_ SG_ 2332688221 TMS_EnvTemp_29 "TMS环境温度";
CM_ SG_ 2332688221 TMS_RequestPower_29 "TMS需求功率";
CM_ SG_ 2332688221 STMS_ThrmStopReason_29 "热管理停机原因";
CM_ SG_ 2332688222 B2T_ControlMode_30 "BMS请求设定模式";
CM_ SG_ 2332688222 TMS_RunState_30 "TMS运行状态";
CM_ SG_ 2332688222 TMS_CommuFault_30 "TMS通信丢失";
CM_ SG_ 2332688222 TMS_ModeConflict_30 "TMS运行模式与BMS控制指令冲突";
CM_ SG_ 2332688222 TMS_MakeBMSStop_30 "TMS致电柜停机故障";
CM_ SG_ 2332688222 TMS_HVRealyState_30 "TMS高压继电器状态";
CM_ SG_ 2332688222 TMS_FaultCode_30 "TMS故障码";
CM_ SG_ 2332688222 TMS_FaultLevel_30 "TMS故障码等级";
CM_ SG_ 2332688222 B2T_TmptSetPoint_30 "BMS请求设定温度";
CM_ SG_ 2332688222 TMS_OutWaterTemp_30 "TMS出水温度";
CM_ SG_ 2332688222 TMS_BackWaterTemp_30 "TMS回水温度";
CM_ SG_ 2332688222 TMS_EnvTemp_30 "TMS环境温度";
CM_ SG_ 2332688222 TMS_RequestPower_30 "TMS需求功率";
CM_ SG_ 2332688222 STMS_ThrmStopReason_30 "热管理停机原因";
CM_ SG_ 2332688223 B2T_ControlMode_31 "BMS请求设定模式";
CM_ SG_ 2332688223 TMS_RunState_31 "TMS运行状态";
CM_ SG_ 2332688223 TMS_CommuFault_31 "TMS通信丢失";
CM_ SG_ 2332688223 TMS_ModeConflict_31 "TMS运行模式与BMS控制指令冲突";
CM_ SG_ 2332688223 TMS_MakeBMSStop_31 "TMS致电柜停机故障";
CM_ SG_ 2332688223 TMS_HVRealyState_31 "TMS高压继电器状态";
CM_ SG_ 2332688223 TMS_FaultCode_31 "TMS故障码";
CM_ SG_ 2332688223 TMS_FaultLevel_31 "TMS故障码等级";
CM_ SG_ 2332688223 B2T_TmptSetPoint_31 "BMS请求设定温度";
CM_ SG_ 2332688223 TMS_OutWaterTemp_31 "TMS出水温度";
CM_ SG_ 2332688223 TMS_BackWaterTemp_31 "TMS回水温度";
CM_ SG_ 2332688223 TMS_EnvTemp_31 "TMS环境温度";
CM_ SG_ 2332688223 TMS_RequestPower_31 "TMS需求功率";
CM_ SG_ 2332688223 STMS_ThrmStopReason_31 "热管理停机原因";
CM_ SG_ 2332688224 B2T_ControlMode_32 "BMS请求设定模式";
CM_ SG_ 2332688224 TMS_RunState_32 "TMS运行状态";
CM_ SG_ 2332688224 TMS_CommuFault_32 "TMS通信丢失";
CM_ SG_ 2332688224 TMS_ModeConflict_32 "TMS运行模式与BMS控制指令冲突";
CM_ SG_ 2332688224 TMS_MakeBMSStop_32 "TMS致电柜停机故障";
CM_ SG_ 2332688224 TMS_HVRealyState_32 "TMS高压继电器状态";
CM_ SG_ 2332688224 TMS_FaultCode_32 "TMS故障码";
CM_ SG_ 2332688224 TMS_FaultLevel_32 "TMS故障码等级";
CM_ SG_ 2332688224 B2T_TmptSetPoint_32 "BMS请求设定温度";
CM_ SG_ 2332688224 TMS_OutWaterTemp_32 "TMS出水温度";
CM_ SG_ 2332688224 TMS_BackWaterTemp_32 "TMS回水温度";
CM_ SG_ 2332688224 TMS_EnvTemp_32 "TMS环境温度";
CM_ SG_ 2332688224 TMS_RequestPower_32 "TMS需求功率";
CM_ SG_ 2332688224 STMS_ThrmStopReason_32 "热管理停机原因";
CM_ SG_ 2332688225 B2T_ControlMode_33 "BMS请求设定模式";
CM_ SG_ 2332688225 TMS_RunState_33 "TMS运行状态";
CM_ SG_ 2332688225 TMS_CommuFault_33 "TMS通信丢失";
CM_ SG_ 2332688225 TMS_ModeConflict_33 "TMS运行模式与BMS控制指令冲突";
CM_ SG_ 2332688225 TMS_MakeBMSStop_33 "TMS致电柜停机故障";
CM_ SG_ 2332688225 TMS_HVRealyState_33 "TMS高压继电器状态";
CM_ SG_ 2332688225 TMS_FaultCode_33 "TMS故障码";
CM_ SG_ 2332688225 TMS_FaultLevel_33 "TMS故障码等级";
CM_ SG_ 2332688225 B2T_TmptSetPoint_33 "BMS请求设定温度";
CM_ SG_ 2332688225 TMS_OutWaterTemp_33 "TMS出水温度";
CM_ SG_ 2332688225 TMS_BackWaterTemp_33 "TMS回水温度";
CM_ SG_ 2332688225 TMS_EnvTemp_33 "TMS环境温度";
CM_ SG_ 2332688225 TMS_RequestPower_33 "TMS需求功率";
CM_ SG_ 2332688225 STMS_ThrmStopReason_33 "热管理停机原因";
CM_ SG_ 2332688226 B2T_ControlMode_34 "BMS请求设定模式";
CM_ SG_ 2332688226 TMS_RunState_34 "TMS运行状态";
CM_ SG_ 2332688226 TMS_CommuFault_34 "TMS通信丢失";
CM_ SG_ 2332688226 TMS_ModeConflict_34 "TMS运行模式与BMS控制指令冲突";
CM_ SG_ 2332688226 TMS_MakeBMSStop_34 "TMS致电柜停机故障";
CM_ SG_ 2332688226 TMS_HVRealyState_34 "TMS高压继电器状态";
CM_ SG_ 2332688226 TMS_FaultCode_34 "TMS故障码";
CM_ SG_ 2332688226 TMS_FaultLevel_34 "TMS故障码等级";
CM_ SG_ 2332688226 B2T_TmptSetPoint_34 "BMS请求设定温度";
CM_ SG_ 2332688226 TMS_OutWaterTemp_34 "TMS出水温度";
CM_ SG_ 2332688226 TMS_BackWaterTemp_34 "TMS回水温度";
CM_ SG_ 2332688226 TMS_EnvTemp_34 "TMS环境温度";
CM_ SG_ 2332688226 TMS_RequestPower_34 "TMS需求功率";
CM_ SG_ 2332688226 STMS_ThrmStopReason_34 "热管理停机原因";
CM_ SG_ 2332688227 B2T_ControlMode_35 "BMS请求设定模式";
CM_ SG_ 2332688227 TMS_RunState_35 "TMS运行状态";
CM_ SG_ 2332688227 TMS_CommuFault_35 "TMS通信丢失";
CM_ SG_ 2332688227 TMS_ModeConflict_35 "TMS运行模式与BMS控制指令冲突";
CM_ SG_ 2332688227 TMS_MakeBMSStop_35 "TMS致电柜停机故障";
CM_ SG_ 2332688227 TMS_HVRealyState_35 "TMS高压继电器状态";
CM_ SG_ 2332688227 TMS_FaultCode_35 "TMS故障码";
CM_ SG_ 2332688227 TMS_FaultLevel_35 "TMS故障码等级";
CM_ SG_ 2332688227 B2T_TmptSetPoint_35 "BMS请求设定温度";
CM_ SG_ 2332688227 TMS_OutWaterTemp_35 "TMS出水温度";
CM_ SG_ 2332688227 TMS_BackWaterTemp_35 "TMS回水温度";
CM_ SG_ 2332688227 TMS_EnvTemp_35 "TMS环境温度";
CM_ SG_ 2332688227 TMS_RequestPower_35 "TMS需求功率";
CM_ SG_ 2332688227 STMS_ThrmStopReason_35 "热管理停机原因";
CM_ SG_ 2332688228 B2T_ControlMode_36 "BMS请求设定模式";
CM_ SG_ 2332688228 TMS_RunState_36 "TMS运行状态";
CM_ SG_ 2332688228 TMS_CommuFault_36 "TMS通信丢失";
CM_ SG_ 2332688228 TMS_ModeConflict_36 "TMS运行模式与BMS控制指令冲突";
CM_ SG_ 2332688228 TMS_MakeBMSStop_36 "TMS致电柜停机故障";
CM_ SG_ 2332688228 TMS_HVRealyState_36 "TMS高压继电器状态";
CM_ SG_ 2332688228 TMS_FaultCode_36 "TMS故障码";
CM_ SG_ 2332688228 TMS_FaultLevel_36 "TMS故障码等级";
CM_ SG_ 2332688228 B2T_TmptSetPoint_36 "BMS请求设定温度";
CM_ SG_ 2332688228 TMS_OutWaterTemp_36 "TMS出水温度";
CM_ SG_ 2332688228 TMS_BackWaterTemp_36 "TMS回水温度";
CM_ SG_ 2332688228 TMS_EnvTemp_36 "TMS环境温度";
CM_ SG_ 2332688228 TMS_RequestPower_36 "TMS需求功率";
CM_ SG_ 2332688228 STMS_ThrmStopReason_36 "热管理停机原因";
CM_ SG_ 2332688229 B2T_ControlMode_37 "BMS请求设定模式";
CM_ SG_ 2332688229 TMS_RunState_37 "TMS运行状态";
CM_ SG_ 2332688229 TMS_CommuFault_37 "TMS通信丢失";
CM_ SG_ 2332688229 TMS_ModeConflict_37 "TMS运行模式与BMS控制指令冲突";
CM_ SG_ 2332688229 TMS_MakeBMSStop_37 "TMS致电柜停机故障";
CM_ SG_ 2332688229 TMS_HVRealyState_37 "TMS高压继电器状态";
CM_ SG_ 2332688229 TMS_FaultCode_37 "TMS故障码";
CM_ SG_ 2332688229 TMS_FaultLevel_37 "TMS故障码等级";
CM_ SG_ 2332688229 B2T_TmptSetPoint_37 "BMS请求设定温度";
CM_ SG_ 2332688229 TMS_OutWaterTemp_37 "TMS出水温度";
CM_ SG_ 2332688229 TMS_BackWaterTemp_37 "TMS回水温度";
CM_ SG_ 2332688229 TMS_EnvTemp_37 "TMS环境温度";
CM_ SG_ 2332688229 TMS_RequestPower_37 "TMS需求功率";
CM_ SG_ 2332688229 STMS_ThrmStopReason_37 "热管理停机原因";
CM_ SG_ 2332688230 B2T_ControlMode_38 "BMS请求设定模式";
CM_ SG_ 2332688230 TMS_RunState_38 "TMS运行状态";
CM_ SG_ 2332688230 TMS_CommuFault_38 "TMS通信丢失";
CM_ SG_ 2332688230 TMS_ModeConflict_38 "TMS运行模式与BMS控制指令冲突";
CM_ SG_ 2332688230 TMS_MakeBMSStop_38 "TMS致电柜停机故障";
CM_ SG_ 2332688230 TMS_HVRealyState_38 "TMS高压继电器状态";
CM_ SG_ 2332688230 TMS_FaultCode_38 "TMS故障码";
CM_ SG_ 2332688230 TMS_FaultLevel_38 "TMS故障码等级";
CM_ SG_ 2332688230 B2T_TmptSetPoint_38 "BMS请求设定温度";
CM_ SG_ 2332688230 TMS_OutWaterTemp_38 "TMS出水温度";
CM_ SG_ 2332688230 TMS_BackWaterTemp_38 "TMS回水温度";
CM_ SG_ 2332688230 TMS_EnvTemp_38 "TMS环境温度";
CM_ SG_ 2332688230 TMS_RequestPower_38 "TMS需求功率";
CM_ SG_ 2332688230 STMS_ThrmStopReason_38 "热管理停机原因";
CM_ SG_ 2332688231 B2T_ControlMode_39 "BMS请求设定模式";
CM_ SG_ 2332688231 TMS_RunState_39 "TMS运行状态";
CM_ SG_ 2332688231 TMS_CommuFault_39 "TMS通信丢失";
CM_ SG_ 2332688231 TMS_ModeConflict_39 "TMS运行模式与BMS控制指令冲突";
CM_ SG_ 2332688231 TMS_MakeBMSStop_39 "TMS致电柜停机故障";
CM_ SG_ 2332688231 TMS_HVRealyState_39 "TMS高压继电器状态";
CM_ SG_ 2332688231 TMS_FaultCode_39 "TMS故障码";
CM_ SG_ 2332688231 TMS_FaultLevel_39 "TMS故障码等级";
CM_ SG_ 2332688231 B2T_TmptSetPoint_39 "BMS请求设定温度";
CM_ SG_ 2332688231 TMS_OutWaterTemp_39 "TMS出水温度";
CM_ SG_ 2332688231 TMS_BackWaterTemp_39 "TMS回水温度";
CM_ SG_ 2332688231 TMS_EnvTemp_39 "TMS环境温度";
CM_ SG_ 2332688231 TMS_RequestPower_39 "TMS需求功率";
CM_ SG_ 2332688231 STMS_ThrmStopReason_39 "热管理停机原因";
CM_ SG_ 2332688232 B2T_ControlMode_40 "BMS请求设定模式";
CM_ SG_ 2332688232 TMS_RunState_40 "TMS运行状态";
CM_ SG_ 2332688232 TMS_CommuFault_40 "TMS通信丢失";
CM_ SG_ 2332688232 TMS_ModeConflict_40 "TMS运行模式与BMS控制指令冲突";
CM_ SG_ 2332688232 TMS_MakeBMSStop_40 "TMS致电柜停机故障";
CM_ SG_ 2332688232 TMS_HVRealyState_40 "TMS高压继电器状态";
CM_ SG_ 2332688232 TMS_FaultCode_40 "TMS故障码";
CM_ SG_ 2332688232 TMS_FaultLevel_40 "TMS故障码等级";
CM_ SG_ 2332688232 B2T_TmptSetPoint_40 "BMS请求设定温度";
CM_ SG_ 2332688232 TMS_OutWaterTemp_40 "TMS出水温度";
CM_ SG_ 2332688232 TMS_BackWaterTemp_40 "TMS回水温度";
CM_ SG_ 2332688232 TMS_EnvTemp_40 "TMS环境温度";
CM_ SG_ 2332688232 TMS_RequestPower_40 "TMS需求功率";
CM_ SG_ 2332688232 STMS_ThrmStopReason_40 "热管理停机原因";
CM_ SG_ 2332688233 B2T_ControlMode_41 "BMS请求设定模式";
CM_ SG_ 2332688233 TMS_RunState_41 "TMS运行状态";
CM_ SG_ 2332688233 TMS_CommuFault_41 "TMS通信丢失";
CM_ SG_ 2332688233 TMS_ModeConflict_41 "TMS运行模式与BMS控制指令冲突";
CM_ SG_ 2332688233 TMS_MakeBMSStop_41 "TMS致电柜停机故障";
CM_ SG_ 2332688233 TMS_HVRealyState_41 "TMS高压继电器状态";
CM_ SG_ 2332688233 TMS_FaultCode_41 "TMS故障码";
CM_ SG_ 2332688233 TMS_FaultLevel_41 "TMS故障码等级";
CM_ SG_ 2332688233 B2T_TmptSetPoint_41 "BMS请求设定温度";
CM_ SG_ 2332688233 TMS_OutWaterTemp_41 "TMS出水温度";
CM_ SG_ 2332688233 TMS_BackWaterTemp_41 "TMS回水温度";
CM_ SG_ 2332688233 TMS_EnvTemp_41 "TMS环境温度";
CM_ SG_ 2332688233 TMS_RequestPower_41 "TMS需求功率";
CM_ SG_ 2332688233 STMS_ThrmStopReason_41 "热管理停机原因";
CM_ SG_ 2332688234 B2T_ControlMode_42 "BMS请求设定模式";
CM_ SG_ 2332688234 TMS_RunState_42 "TMS运行状态";
CM_ SG_ 2332688234 TMS_CommuFault_42 "TMS通信丢失";
CM_ SG_ 2332688234 TMS_ModeConflict_42 "TMS运行模式与BMS控制指令冲突";
CM_ SG_ 2332688234 TMS_MakeBMSStop_42 "TMS致电柜停机故障";
CM_ SG_ 2332688234 TMS_HVRealyState_42 "TMS高压继电器状态";
CM_ SG_ 2332688234 TMS_FaultCode_42 "TMS故障码";
CM_ SG_ 2332688234 TMS_FaultLevel_42 "TMS故障码等级";
CM_ SG_ 2332688234 B2T_TmptSetPoint_42 "BMS请求设定温度";
CM_ SG_ 2332688234 TMS_OutWaterTemp_42 "TMS出水温度";
CM_ SG_ 2332688234 TMS_BackWaterTemp_42 "TMS回水温度";
CM_ SG_ 2332688234 TMS_EnvTemp_42 "TMS环境温度";
CM_ SG_ 2332688234 TMS_RequestPower_42 "TMS需求功率";
CM_ SG_ 2332688234 STMS_ThrmStopReason_42 "热管理停机原因";
CM_ SG_ 2332688235 B2T_ControlMode_43 "BMS请求设定模式";
CM_ SG_ 2332688235 TMS_RunState_43 "TMS运行状态";
CM_ SG_ 2332688235 TMS_CommuFault_43 "TMS通信丢失";
CM_ SG_ 2332688235 TMS_ModeConflict_43 "TMS运行模式与BMS控制指令冲突";
CM_ SG_ 2332688235 TMS_MakeBMSStop_43 "TMS致电柜停机故障";
CM_ SG_ 2332688235 TMS_HVRealyState_43 "TMS高压继电器状态";
CM_ SG_ 2332688235 TMS_FaultCode_43 "TMS故障码";
CM_ SG_ 2332688235 TMS_FaultLevel_43 "TMS故障码等级";
CM_ SG_ 2332688235 B2T_TmptSetPoint_43 "BMS请求设定温度";
CM_ SG_ 2332688235 TMS_OutWaterTemp_43 "TMS出水温度";
CM_ SG_ 2332688235 TMS_BackWaterTemp_43 "TMS回水温度";
CM_ SG_ 2332688235 TMS_EnvTemp_43 "TMS环境温度";
CM_ SG_ 2332688235 TMS_RequestPower_43 "TMS需求功率";
CM_ SG_ 2332688235 STMS_ThrmStopReason_43 "热管理停机原因";
CM_ SG_ 2332688236 B2T_ControlMode_44 "BMS请求设定模式";
CM_ SG_ 2332688236 TMS_RunState_44 "TMS运行状态";
CM_ SG_ 2332688236 TMS_CommuFault_44 "TMS通信丢失";
CM_ SG_ 2332688236 TMS_ModeConflict_44 "TMS运行模式与BMS控制指令冲突";
CM_ SG_ 2332688236 TMS_MakeBMSStop_44 "TMS致电柜停机故障";
CM_ SG_ 2332688236 TMS_HVRealyState_44 "TMS高压继电器状态";
CM_ SG_ 2332688236 TMS_FaultCode_44 "TMS故障码";
CM_ SG_ 2332688236 TMS_FaultLevel_44 "TMS故障码等级";
CM_ SG_ 2332688236 B2T_TmptSetPoint_44 "BMS请求设定温度";
CM_ SG_ 2332688236 TMS_OutWaterTemp_44 "TMS出水温度";
CM_ SG_ 2332688236 TMS_BackWaterTemp_44 "TMS回水温度";
CM_ SG_ 2332688236 TMS_EnvTemp_44 "TMS环境温度";
CM_ SG_ 2332688236 TMS_RequestPower_44 "TMS需求功率";
CM_ SG_ 2332688236 STMS_ThrmStopReason_44 "热管理停机原因";
CM_ SG_ 2332688237 B2T_ControlMode_45 "BMS请求设定模式";
CM_ SG_ 2332688237 TMS_RunState_45 "TMS运行状态";
CM_ SG_ 2332688237 TMS_CommuFault_45 "TMS通信丢失";
CM_ SG_ 2332688237 TMS_ModeConflict_45 "TMS运行模式与BMS控制指令冲突";
CM_ SG_ 2332688237 TMS_MakeBMSStop_45 "TMS致电柜停机故障";
CM_ SG_ 2332688237 TMS_HVRealyState_45 "TMS高压继电器状态";
CM_ SG_ 2332688237 TMS_FaultCode_45 "TMS故障码";
CM_ SG_ 2332688237 TMS_FaultLevel_45 "TMS故障码等级";
CM_ SG_ 2332688237 B2T_TmptSetPoint_45 "BMS请求设定温度";
CM_ SG_ 2332688237 TMS_OutWaterTemp_45 "TMS出水温度";
CM_ SG_ 2332688237 TMS_BackWaterTemp_45 "TMS回水温度";
CM_ SG_ 2332688237 TMS_EnvTemp_45 "TMS环境温度";
CM_ SG_ 2332688237 TMS_RequestPower_45 "TMS需求功率";
CM_ SG_ 2332688237 STMS_ThrmStopReason_45 "热管理停机原因";
CM_ SG_ 2332688238 B2T_ControlMode_46 "BMS请求设定模式";
CM_ SG_ 2332688238 TMS_RunState_46 "TMS运行状态";
CM_ SG_ 2332688238 TMS_CommuFault_46 "TMS通信丢失";
CM_ SG_ 2332688238 TMS_ModeConflict_46 "TMS运行模式与BMS控制指令冲突";
CM_ SG_ 2332688238 TMS_MakeBMSStop_46 "TMS致电柜停机故障";
CM_ SG_ 2332688238 TMS_HVRealyState_46 "TMS高压继电器状态";
CM_ SG_ 2332688238 TMS_FaultCode_46 "TMS故障码";
CM_ SG_ 2332688238 TMS_FaultLevel_46 "TMS故障码等级";
CM_ SG_ 2332688238 B2T_TmptSetPoint_46 "BMS请求设定温度";
CM_ SG_ 2332688238 TMS_OutWaterTemp_46 "TMS出水温度";
CM_ SG_ 2332688238 TMS_BackWaterTemp_46 "TMS回水温度";
CM_ SG_ 2332688238 TMS_EnvTemp_46 "TMS环境温度";
CM_ SG_ 2332688238 TMS_RequestPower_46 "TMS需求功率";
CM_ SG_ 2332688238 STMS_ThrmStopReason_46 "热管理停机原因";
CM_ SG_ 2332688239 B2T_ControlMode_47 "BMS请求设定模式";
CM_ SG_ 2332688239 TMS_RunState_47 "TMS运行状态";
CM_ SG_ 2332688239 TMS_CommuFault_47 "TMS通信丢失";
CM_ SG_ 2332688239 TMS_ModeConflict_47 "TMS运行模式与BMS控制指令冲突";
CM_ SG_ 2332688239 TMS_MakeBMSStop_47 "TMS致电柜停机故障";
CM_ SG_ 2332688239 TMS_HVRealyState_47 "TMS高压继电器状态";
CM_ SG_ 2332688239 TMS_FaultCode_47 "TMS故障码";
CM_ SG_ 2332688239 TMS_FaultLevel_47 "TMS故障码等级";
CM_ SG_ 2332688239 B2T_TmptSetPoint_47 "BMS请求设定温度";
CM_ SG_ 2332688239 TMS_OutWaterTemp_47 "TMS出水温度";
CM_ SG_ 2332688239 TMS_BackWaterTemp_47 "TMS回水温度";
CM_ SG_ 2332688239 TMS_EnvTemp_47 "TMS环境温度";
CM_ SG_ 2332688239 TMS_RequestPower_47 "TMS需求功率";
CM_ SG_ 2332688239 STMS_ThrmStopReason_47 "热管理停机原因";
CM_ SG_ 2332688240 B2T_ControlMode_48 "BMS请求设定模式";
CM_ SG_ 2332688240 TMS_RunState_48 "TMS运行状态";
CM_ SG_ 2332688240 TMS_CommuFault_48 "TMS通信丢失";
CM_ SG_ 2332688240 TMS_ModeConflict_48 "TMS运行模式与BMS控制指令冲突";
CM_ SG_ 2332688240 TMS_MakeBMSStop_48 "TMS致电柜停机故障";
CM_ SG_ 2332688240 TMS_HVRealyState_48 "TMS高压继电器状态";
CM_ SG_ 2332688240 TMS_FaultCode_48 "TMS故障码";
CM_ SG_ 2332688240 TMS_FaultLevel_48 "TMS故障码等级";
CM_ SG_ 2332688240 B2T_TmptSetPoint_48 "BMS请求设定温度";
CM_ SG_ 2332688240 TMS_OutWaterTemp_48 "TMS出水温度";
CM_ SG_ 2332688240 TMS_BackWaterTemp_48 "TMS回水温度";
CM_ SG_ 2332688240 TMS_EnvTemp_48 "TMS环境温度";
CM_ SG_ 2332688240 TMS_RequestPower_48 "TMS需求功率";
CM_ SG_ 2332688240 STMS_ThrmStopReason_48 "热管理停机原因";
CM_ SG_ 2332688241 B2T_ControlMode_49 "BMS请求设定模式";
CM_ SG_ 2332688241 TMS_RunState_49 "TMS运行状态";
CM_ SG_ 2332688241 TMS_CommuFault_49 "TMS通信丢失";
CM_ SG_ 2332688241 TMS_ModeConflict_49 "TMS运行模式与BMS控制指令冲突";
CM_ SG_ 2332688241 TMS_MakeBMSStop_49 "TMS致电柜停机故障";
CM_ SG_ 2332688241 TMS_HVRealyState_49 "TMS高压继电器状态";
CM_ SG_ 2332688241 TMS_FaultCode_49 "TMS故障码";
CM_ SG_ 2332688241 TMS_FaultLevel_49 "TMS故障码等级";
CM_ SG_ 2332688241 B2T_TmptSetPoint_49 "BMS请求设定温度";
CM_ SG_ 2332688241 TMS_OutWaterTemp_49 "TMS出水温度";
CM_ SG_ 2332688241 TMS_BackWaterTemp_49 "TMS回水温度";
CM_ SG_ 2332688241 TMS_EnvTemp_49 "TMS环境温度";
CM_ SG_ 2332688241 TMS_RequestPower_49 "TMS需求功率";
CM_ SG_ 2332688241 STMS_ThrmStopReason_49 "热管理停机原因";
CM_ SG_ 2332688242 B2T_ControlMode_50 "BMS请求设定模式";
CM_ SG_ 2332688242 TMS_RunState_50 "TMS运行状态";
CM_ SG_ 2332688242 TMS_CommuFault_50 "TMS通信丢失";
CM_ SG_ 2332688242 TMS_ModeConflict_50 "TMS运行模式与BMS控制指令冲突";
CM_ SG_ 2332688242 TMS_MakeBMSStop_50 "TMS致电柜停机故障";
CM_ SG_ 2332688242 TMS_HVRealyState_50 "TMS高压继电器状态";
CM_ SG_ 2332688242 TMS_FaultCode_50 "TMS故障码";
CM_ SG_ 2332688242 TMS_FaultLevel_50 "TMS故障码等级";
CM_ SG_ 2332688242 B2T_TmptSetPoint_50 "BMS请求设定温度";
CM_ SG_ 2332688242 TMS_OutWaterTemp_50 "TMS出水温度";
CM_ SG_ 2332688242 TMS_BackWaterTemp_50 "TMS回水温度";
CM_ SG_ 2332688242 TMS_EnvTemp_50 "TMS环境温度";
CM_ SG_ 2332688242 TMS_RequestPower_50 "TMS需求功率";
CM_ SG_ 2332688242 STMS_ThrmStopReason_50 "热管理停机原因";
CM_ SG_ 2332688243 B2T_ControlMode_51 "BMS请求设定模式";
CM_ SG_ 2332688243 TMS_RunState_51 "TMS运行状态";
CM_ SG_ 2332688243 TMS_CommuFault_51 "TMS通信丢失";
CM_ SG_ 2332688243 TMS_ModeConflict_51 "TMS运行模式与BMS控制指令冲突";
CM_ SG_ 2332688243 TMS_MakeBMSStop_51 "TMS致电柜停机故障";
CM_ SG_ 2332688243 TMS_HVRealyState_51 "TMS高压继电器状态";
CM_ SG_ 2332688243 TMS_FaultCode_51 "TMS故障码";
CM_ SG_ 2332688243 TMS_FaultLevel_51 "TMS故障码等级";
CM_ SG_ 2332688243 B2T_TmptSetPoint_51 "BMS请求设定温度";
CM_ SG_ 2332688243 TMS_OutWaterTemp_51 "TMS出水温度";
CM_ SG_ 2332688243 TMS_BackWaterTemp_51 "TMS回水温度";
CM_ SG_ 2332688243 TMS_EnvTemp_51 "TMS环境温度";
CM_ SG_ 2332688243 TMS_RequestPower_51 "TMS需求功率";
CM_ SG_ 2332688243 STMS_ThrmStopReason_51 "热管理停机原因";
CM_ SG_ 2332688244 B2T_ControlMode_52 "BMS请求设定模式";
CM_ SG_ 2332688244 TMS_RunState_52 "TMS运行状态";
CM_ SG_ 2332688244 TMS_CommuFault_52 "TMS通信丢失";
CM_ SG_ 2332688244 TMS_ModeConflict_52 "TMS运行模式与BMS控制指令冲突";
CM_ SG_ 2332688244 TMS_MakeBMSStop_52 "TMS致电柜停机故障";
CM_ SG_ 2332688244 TMS_HVRealyState_52 "TMS高压继电器状态";
CM_ SG_ 2332688244 TMS_FaultCode_52 "TMS故障码";
CM_ SG_ 2332688244 TMS_FaultLevel_52 "TMS故障码等级";
CM_ SG_ 2332688244 B2T_TmptSetPoint_52 "BMS请求设定温度";
CM_ SG_ 2332688244 TMS_OutWaterTemp_52 "TMS出水温度";
CM_ SG_ 2332688244 TMS_BackWaterTemp_52 "TMS回水温度";
CM_ SG_ 2332688244 TMS_EnvTemp_52 "TMS环境温度";
CM_ SG_ 2332688244 TMS_RequestPower_52 "TMS需求功率";
CM_ SG_ 2332688244 STMS_ThrmStopReason_52 "热管理停机原因";
CM_ SG_ 2332688245 B2T_ControlMode_53 "BMS请求设定模式";
CM_ SG_ 2332688245 TMS_RunState_53 "TMS运行状态";
CM_ SG_ 2332688245 TMS_CommuFault_53 "TMS通信丢失";
CM_ SG_ 2332688245 TMS_ModeConflict_53 "TMS运行模式与BMS控制指令冲突";
CM_ SG_ 2332688245 TMS_MakeBMSStop_53 "TMS致电柜停机故障";
CM_ SG_ 2332688245 TMS_HVRealyState_53 "TMS高压继电器状态";
CM_ SG_ 2332688245 TMS_FaultCode_53 "TMS故障码";
CM_ SG_ 2332688245 TMS_FaultLevel_53 "TMS故障码等级";
CM_ SG_ 2332688245 B2T_TmptSetPoint_53 "BMS请求设定温度";
CM_ SG_ 2332688245 TMS_OutWaterTemp_53 "TMS出水温度";
CM_ SG_ 2332688245 TMS_BackWaterTemp_53 "TMS回水温度";
CM_ SG_ 2332688245 TMS_EnvTemp_53 "TMS环境温度";
CM_ SG_ 2332688245 TMS_RequestPower_53 "TMS需求功率";
CM_ SG_ 2332688245 STMS_ThrmStopReason_53 "热管理停机原因";
CM_ SG_ 2332688246 B2T_ControlMode_54 "BMS请求设定模式";
CM_ SG_ 2332688246 TMS_RunState_54 "TMS运行状态";
CM_ SG_ 2332688246 TMS_CommuFault_54 "TMS通信丢失";
CM_ SG_ 2332688246 TMS_ModeConflict_54 "TMS运行模式与BMS控制指令冲突";
CM_ SG_ 2332688246 TMS_MakeBMSStop_54 "TMS致电柜停机故障";
CM_ SG_ 2332688246 TMS_HVRealyState_54 "TMS高压继电器状态";
CM_ SG_ 2332688246 TMS_FaultCode_54 "TMS故障码";
CM_ SG_ 2332688246 TMS_FaultLevel_54 "TMS故障码等级";
CM_ SG_ 2332688246 B2T_TmptSetPoint_54 "BMS请求设定温度";
CM_ SG_ 2332688246 TMS_OutWaterTemp_54 "TMS出水温度";
CM_ SG_ 2332688246 TMS_BackWaterTemp_54 "TMS回水温度";
CM_ SG_ 2332688246 TMS_EnvTemp_54 "TMS环境温度";
CM_ SG_ 2332688246 TMS_RequestPower_54 "TMS需求功率";
CM_ SG_ 2332688246 STMS_ThrmStopReason_54 "热管理停机原因";
CM_ SG_ 2332688247 B2T_ControlMode_55 "BMS请求设定模式";
CM_ SG_ 2332688247 TMS_RunState_55 "TMS运行状态";
CM_ SG_ 2332688247 TMS_CommuFault_55 "TMS通信丢失";
CM_ SG_ 2332688247 TMS_ModeConflict_55 "TMS运行模式与BMS控制指令冲突";
CM_ SG_ 2332688247 TMS_MakeBMSStop_55 "TMS致电柜停机故障";
CM_ SG_ 2332688247 TMS_HVRealyState_55 "TMS高压继电器状态";
CM_ SG_ 2332688247 TMS_FaultCode_55 "TMS故障码";
CM_ SG_ 2332688247 TMS_FaultLevel_55 "TMS故障码等级";
CM_ SG_ 2332688247 B2T_TmptSetPoint_55 "BMS请求设定温度";
CM_ SG_ 2332688247 TMS_OutWaterTemp_55 "TMS出水温度";
CM_ SG_ 2332688247 TMS_BackWaterTemp_55 "TMS回水温度";
CM_ SG_ 2332688247 TMS_EnvTemp_55 "TMS环境温度";
CM_ SG_ 2332688247 TMS_RequestPower_55 "TMS需求功率";
CM_ SG_ 2332688247 STMS_ThrmStopReason_55 "热管理停机原因";
CM_ SG_ 2332688248 B2T_ControlMode_56 "BMS请求设定模式";
CM_ SG_ 2332688248 TMS_RunState_56 "TMS运行状态";
CM_ SG_ 2332688248 TMS_CommuFault_56 "TMS通信丢失";
CM_ SG_ 2332688248 TMS_ModeConflict_56 "TMS运行模式与BMS控制指令冲突";
CM_ SG_ 2332688248 TMS_MakeBMSStop_56 "TMS致电柜停机故障";
CM_ SG_ 2332688248 TMS_HVRealyState_56 "TMS高压继电器状态";
CM_ SG_ 2332688248 TMS_FaultCode_56 "TMS故障码";
CM_ SG_ 2332688248 TMS_FaultLevel_56 "TMS故障码等级";
CM_ SG_ 2332688248 B2T_TmptSetPoint_56 "BMS请求设定温度";
CM_ SG_ 2332688248 TMS_OutWaterTemp_56 "TMS出水温度";
CM_ SG_ 2332688248 TMS_BackWaterTemp_56 "TMS回水温度";
CM_ SG_ 2332688248 TMS_EnvTemp_56 "TMS环境温度";
CM_ SG_ 2332688248 TMS_RequestPower_56 "TMS需求功率";
CM_ SG_ 2332688248 STMS_ThrmStopReason_56 "热管理停机原因";
CM_ SG_ 2332688249 B2T_ControlMode_57 "BMS请求设定模式";
CM_ SG_ 2332688249 TMS_RunState_57 "TMS运行状态";
CM_ SG_ 2332688249 TMS_CommuFault_57 "TMS通信丢失";
CM_ SG_ 2332688249 TMS_ModeConflict_57 "TMS运行模式与BMS控制指令冲突";
CM_ SG_ 2332688249 TMS_MakeBMSStop_57 "TMS致电柜停机故障";
CM_ SG_ 2332688249 TMS_HVRealyState_57 "TMS高压继电器状态";
CM_ SG_ 2332688249 TMS_FaultCode_57 "TMS故障码";
CM_ SG_ 2332688249 TMS_FaultLevel_57 "TMS故障码等级";
CM_ SG_ 2332688249 B2T_TmptSetPoint_57 "BMS请求设定温度";
CM_ SG_ 2332688249 TMS_OutWaterTemp_57 "TMS出水温度";
CM_ SG_ 2332688249 TMS_BackWaterTemp_57 "TMS回水温度";
CM_ SG_ 2332688249 TMS_EnvTemp_57 "TMS环境温度";
CM_ SG_ 2332688249 TMS_RequestPower_57 "TMS需求功率";
CM_ SG_ 2332688249 STMS_ThrmStopReason_57 "热管理停机原因";
CM_ SG_ 2332688250 B2T_ControlMode_58 "BMS请求设定模式";
CM_ SG_ 2332688250 TMS_RunState_58 "TMS运行状态";
CM_ SG_ 2332688250 TMS_CommuFault_58 "TMS通信丢失";
CM_ SG_ 2332688250 TMS_ModeConflict_58 "TMS运行模式与BMS控制指令冲突";
CM_ SG_ 2332688250 TMS_MakeBMSStop_58 "TMS致电柜停机故障";
CM_ SG_ 2332688250 TMS_HVRealyState_58 "TMS高压继电器状态";
CM_ SG_ 2332688250 TMS_FaultCode_58 "TMS故障码";
CM_ SG_ 2332688250 TMS_FaultLevel_58 "TMS故障码等级";
CM_ SG_ 2332688250 B2T_TmptSetPoint_58 "BMS请求设定温度";
CM_ SG_ 2332688250 TMS_OutWaterTemp_58 "TMS出水温度";
CM_ SG_ 2332688250 TMS_BackWaterTemp_58 "TMS回水温度";
CM_ SG_ 2332688250 TMS_EnvTemp_58 "TMS环境温度";
CM_ SG_ 2332688250 TMS_RequestPower_58 "TMS需求功率";
CM_ SG_ 2332688250 STMS_ThrmStopReason_58 "热管理停机原因";
CM_ SG_ 2332688251 B2T_ControlMode_59 "BMS请求设定模式";
CM_ SG_ 2332688251 TMS_RunState_59 "TMS运行状态";
CM_ SG_ 2332688251 TMS_CommuFault_59 "TMS通信丢失";
CM_ SG_ 2332688251 TMS_ModeConflict_59 "TMS运行模式与BMS控制指令冲突";
CM_ SG_ 2332688251 TMS_MakeBMSStop_59 "TMS致电柜停机故障";
CM_ SG_ 2332688251 TMS_HVRealyState_59 "TMS高压继电器状态";
CM_ SG_ 2332688251 TMS_FaultCode_59 "TMS故障码";
CM_ SG_ 2332688251 TMS_FaultLevel_59 "TMS故障码等级";
CM_ SG_ 2332688251 B2T_TmptSetPoint_59 "BMS请求设定温度";
CM_ SG_ 2332688251 TMS_OutWaterTemp_59 "TMS出水温度";
CM_ SG_ 2332688251 TMS_BackWaterTemp_59 "TMS回水温度";
CM_ SG_ 2332688251 TMS_EnvTemp_59 "TMS环境温度";
CM_ SG_ 2332688251 TMS_RequestPower_59 "TMS需求功率";
CM_ SG_ 2332688251 STMS_ThrmStopReason_59 "热管理停机原因";
CM_ SG_ 2332688252 B2T_ControlMode_60 "BMS请求设定模式";
CM_ SG_ 2332688252 TMS_RunState_60 "TMS运行状态";
CM_ SG_ 2332688252 TMS_CommuFault_60 "TMS通信丢失";
CM_ SG_ 2332688252 TMS_ModeConflict_60 "TMS运行模式与BMS控制指令冲突";
CM_ SG_ 2332688252 TMS_MakeBMSStop_60 "TMS致电柜停机故障";
CM_ SG_ 2332688252 TMS_HVRealyState_60 "TMS高压继电器状态";
CM_ SG_ 2332688252 TMS_FaultCode_60 "TMS故障码";
CM_ SG_ 2332688252 TMS_FaultLevel_60 "TMS故障码等级";
CM_ SG_ 2332688252 B2T_TmptSetPoint_60 "BMS请求设定温度";
CM_ SG_ 2332688252 TMS_OutWaterTemp_60 "TMS出水温度";
CM_ SG_ 2332688252 TMS_BackWaterTemp_60 "TMS回水温度";
CM_ SG_ 2332688252 TMS_EnvTemp_60 "TMS环境温度";
CM_ SG_ 2332688252 TMS_RequestPower_60 "TMS需求功率";
CM_ SG_ 2332688252 STMS_ThrmStopReason_60 "热管理停机原因";
CM_ SG_ 2332688253 B2T_ControlMode_61 "BMS请求设定模式";
CM_ SG_ 2332688253 TMS_RunState_61 "TMS运行状态";
CM_ SG_ 2332688253 TMS_CommuFault_61 "TMS通信丢失";
CM_ SG_ 2332688253 TMS_ModeConflict_61 "TMS运行模式与BMS控制指令冲突";
CM_ SG_ 2332688253 TMS_MakeBMSStop_61 "TMS致电柜停机故障";
CM_ SG_ 2332688253 TMS_HVRealyState_61 "TMS高压继电器状态";
CM_ SG_ 2332688253 TMS_FaultCode_61 "TMS故障码";
CM_ SG_ 2332688253 TMS_FaultLevel_61 "TMS故障码等级";
CM_ SG_ 2332688253 B2T_TmptSetPoint_61 "BMS请求设定温度";
CM_ SG_ 2332688253 TMS_OutWaterTemp_61 "TMS出水温度";
CM_ SG_ 2332688253 TMS_BackWaterTemp_61 "TMS回水温度";
CM_ SG_ 2332688253 TMS_EnvTemp_61 "TMS环境温度";
CM_ SG_ 2332688253 TMS_RequestPower_61 "TMS需求功率";
CM_ SG_ 2332688253 STMS_ThrmStopReason_61 "热管理停机原因";
CM_ SG_ 2332688254 B2T_ControlMode_62 "BMS请求设定模式";
CM_ SG_ 2332688254 TMS_RunState_62 "TMS运行状态";
CM_ SG_ 2332688254 TMS_CommuFault_62 "TMS通信丢失";
CM_ SG_ 2332688254 TMS_ModeConflict_62 "TMS运行模式与BMS控制指令冲突";
CM_ SG_ 2332688254 TMS_MakeBMSStop_62 "TMS致电柜停机故障";
CM_ SG_ 2332688254 TMS_HVRealyState_62 "TMS高压继电器状态";
CM_ SG_ 2332688254 TMS_FaultCode_62 "TMS故障码";
CM_ SG_ 2332688254 TMS_FaultLevel_62 "TMS故障码等级";
CM_ SG_ 2332688254 B2T_TmptSetPoint_62 "BMS请求设定温度";
CM_ SG_ 2332688254 TMS_OutWaterTemp_62 "TMS出水温度";
CM_ SG_ 2332688254 TMS_BackWaterTemp_62 "TMS回水温度";
CM_ SG_ 2332688254 TMS_EnvTemp_62 "TMS环境温度";
CM_ SG_ 2332688254 TMS_RequestPower_62 "TMS需求功率";
CM_ SG_ 2332688254 STMS_ThrmStopReason_62 "热管理停机原因";
CM_ SG_ 2332688255 B2T_ControlMode_63 "BMS请求设定模式";
CM_ SG_ 2332688255 TMS_RunState_63 "TMS运行状态";
CM_ SG_ 2332688255 TMS_CommuFault_63 "TMS通信丢失";
CM_ SG_ 2332688255 TMS_ModeConflict_63 "TMS运行模式与BMS控制指令冲突";
CM_ SG_ 2332688255 TMS_MakeBMSStop_63 "TMS致电柜停机故障";
CM_ SG_ 2332688255 TMS_HVRealyState_63 "TMS高压继电器状态";
CM_ SG_ 2332688255 TMS_FaultCode_63 "TMS故障码";
CM_ SG_ 2332688255 TMS_FaultLevel_63 "TMS故障码等级";
CM_ SG_ 2332688255 B2T_TmptSetPoint_63 "BMS请求设定温度";
CM_ SG_ 2332688255 TMS_OutWaterTemp_63 "TMS出水温度";
CM_ SG_ 2332688255 TMS_BackWaterTemp_63 "TMS回水温度";
CM_ SG_ 2332688255 TMS_EnvTemp_63 "TMS环境温度";
CM_ SG_ 2332688255 TMS_RequestPower_63 "TMS需求功率";
CM_ SG_ 2332688255 STMS_ThrmStopReason_63 "热管理停机原因";
CM_ SG_ 2332753729 FireFault_Level1_01 "一级消防故障";
CM_ SG_ 2332753729 FireFault_Level2_01 "二级消防故障";
CM_ SG_ 2332753729 TempState_01 "温感状态";
CM_ SG_ 2332753729 FogState_01 "烟感状态";
CM_ SG_ 2332753729 AerosolState_01 "气溶胶状态";
CM_ SG_ 2332753729 AerosolFaultState_01 "气溶胶故障状态";
CM_ SG_ 2332753729 DoorState_01 "门禁状态";
CM_ SG_ 2332753729 ControlBoxFanState_01 "主控箱风机状态";
CM_ SG_ 2332753729 ControlBoxTempHighWarning_01 "主控箱高温告警";
CM_ SG_ 2332753729 PowerSWState_01 "单柜开关状态（门把手上的钥匙开关）";
CM_ SG_ 2332753729 FaultClearCommand_01 "故障清除指令";
CM_ SG_ 2332753730 FireFault_Level1_02 "一级消防故障";
CM_ SG_ 2332753730 FireFault_Level2_02 "二级消防故障";
CM_ SG_ 2332753730 TempState_02 "温感状态";
CM_ SG_ 2332753730 FogState_02 "烟感状态";
CM_ SG_ 2332753730 AerosolState_02 "气溶胶状态";
CM_ SG_ 2332753730 AerosolFaultState_02 "气溶胶故障状态";
CM_ SG_ 2332753730 DoorState_02 "门禁状态";
CM_ SG_ 2332753730 ControlBoxFanState_02 "主控箱风机状态";
CM_ SG_ 2332753730 ControlBoxTempHighWarning_02 "主控箱高温告警";
CM_ SG_ 2332753730 PowerSWState_02 "单柜开关状态（门把手上的钥匙开关）";
CM_ SG_ 2332753730 FaultClearCommand_02 "故障清除指令";
CM_ SG_ 2332753731 FireFault_Level1_03 "一级消防故障";
CM_ SG_ 2332753731 FireFault_Level2_03 "二级消防故障";
CM_ SG_ 2332753731 TempState_03 "温感状态";
CM_ SG_ 2332753731 FogState_03 "烟感状态";
CM_ SG_ 2332753731 AerosolState_03 "气溶胶状态";
CM_ SG_ 2332753731 AerosolFaultState_03 "气溶胶故障状态";
CM_ SG_ 2332753731 DoorState_03 "门禁状态";
CM_ SG_ 2332753731 ControlBoxFanState_03 "主控箱风机状态";
CM_ SG_ 2332753731 ControlBoxTempHighWarning_03 "主控箱高温告警";
CM_ SG_ 2332753731 PowerSWState_03 "单柜开关状态（门把手上的钥匙开关）";
CM_ SG_ 2332753731 FaultClearCommand_03 "故障清除指令";
CM_ SG_ 2332753732 FireFault_Level1_04 "一级消防故障";
CM_ SG_ 2332753732 FireFault_Level2_04 "二级消防故障";
CM_ SG_ 2332753732 TempState_04 "温感状态";
CM_ SG_ 2332753732 FogState_04 "烟感状态";
CM_ SG_ 2332753732 AerosolState_04 "气溶胶状态";
CM_ SG_ 2332753732 AerosolFaultState_04 "气溶胶故障状态";
CM_ SG_ 2332753732 DoorState_04 "门禁状态";
CM_ SG_ 2332753732 ControlBoxFanState_04 "主控箱风机状态";
CM_ SG_ 2332753732 ControlBoxTempHighWarning_04 "主控箱高温告警";
CM_ SG_ 2332753732 PowerSWState_04 "单柜开关状态（门把手上的钥匙开关）";
CM_ SG_ 2332753732 FaultClearCommand_04 "故障清除指令";
CM_ SG_ 2332753733 FireFault_Level1_05 "一级消防故障";
CM_ SG_ 2332753733 FireFault_Level2_05 "二级消防故障";
CM_ SG_ 2332753733 TempState_05 "温感状态";
CM_ SG_ 2332753733 FogState_05 "烟感状态";
CM_ SG_ 2332753733 AerosolState_05 "气溶胶状态";
CM_ SG_ 2332753733 AerosolFaultState_05 "气溶胶故障状态";
CM_ SG_ 2332753733 DoorState_05 "门禁状态";
CM_ SG_ 2332753733 ControlBoxFanState_05 "主控箱风机状态";
CM_ SG_ 2332753733 ControlBoxTempHighWarning_05 "主控箱高温告警";
CM_ SG_ 2332753733 PowerSWState_05 "单柜开关状态（门把手上的钥匙开关）";
CM_ SG_ 2332753733 FaultClearCommand_05 "故障清除指令";
CM_ SG_ 2332753734 FireFault_Level1_06 "一级消防故障";
CM_ SG_ 2332753734 FireFault_Level2_06 "二级消防故障";
CM_ SG_ 2332753734 TempState_06 "温感状态";
CM_ SG_ 2332753734 FogState_06 "烟感状态";
CM_ SG_ 2332753734 AerosolState_06 "气溶胶状态";
CM_ SG_ 2332753734 AerosolFaultState_06 "气溶胶故障状态";
CM_ SG_ 2332753734 DoorState_06 "门禁状态";
CM_ SG_ 2332753734 ControlBoxFanState_06 "主控箱风机状态";
CM_ SG_ 2332753734 ControlBoxTempHighWarning_06 "主控箱高温告警";
CM_ SG_ 2332753734 PowerSWState_06 "单柜开关状态（门把手上的钥匙开关）";
CM_ SG_ 2332753734 FaultClearCommand_06 "故障清除指令";
CM_ SG_ 2332753735 FireFault_Level1_07 "一级消防故障";
CM_ SG_ 2332753735 FireFault_Level2_07 "二级消防故障";
CM_ SG_ 2332753735 TempState_07 "温感状态";
CM_ SG_ 2332753735 FogState_07 "烟感状态";
CM_ SG_ 2332753735 AerosolState_07 "气溶胶状态";
CM_ SG_ 2332753735 AerosolFaultState_07 "气溶胶故障状态";
CM_ SG_ 2332753735 DoorState_07 "门禁状态";
CM_ SG_ 2332753735 ControlBoxFanState_07 "主控箱风机状态";
CM_ SG_ 2332753735 ControlBoxTempHighWarning_07 "主控箱高温告警";
CM_ SG_ 2332753735 PowerSWState_07 "单柜开关状态（门把手上的钥匙开关）";
CM_ SG_ 2332753735 FaultClearCommand_07 "故障清除指令";
CM_ SG_ 2332753736 FireFault_Level1_08 "一级消防故障";
CM_ SG_ 2332753736 FireFault_Level2_08 "二级消防故障";
CM_ SG_ 2332753736 TempState_08 "温感状态";
CM_ SG_ 2332753736 FogState_08 "烟感状态";
CM_ SG_ 2332753736 AerosolState_08 "气溶胶状态";
CM_ SG_ 2332753736 AerosolFaultState_08 "气溶胶故障状态";
CM_ SG_ 2332753736 DoorState_08 "门禁状态";
CM_ SG_ 2332753736 ControlBoxFanState_08 "主控箱风机状态";
CM_ SG_ 2332753736 ControlBoxTempHighWarning_08 "主控箱高温告警";
CM_ SG_ 2332753736 PowerSWState_08 "单柜开关状态（门把手上的钥匙开关）";
CM_ SG_ 2332753736 FaultClearCommand_08 "故障清除指令";
CM_ SG_ 2332753737 FireFault_Level1_09 "一级消防故障";
CM_ SG_ 2332753737 FireFault_Level2_09 "二级消防故障";
CM_ SG_ 2332753737 TempState_09 "温感状态";
CM_ SG_ 2332753737 FogState_09 "烟感状态";
CM_ SG_ 2332753737 AerosolState_09 "气溶胶状态";
CM_ SG_ 2332753737 AerosolFaultState_09 "气溶胶故障状态";
CM_ SG_ 2332753737 DoorState_09 "门禁状态";
CM_ SG_ 2332753737 ControlBoxFanState_09 "主控箱风机状态";
CM_ SG_ 2332753737 ControlBoxTempHighWarning_09 "主控箱高温告警";
CM_ SG_ 2332753737 PowerSWState_09 "单柜开关状态（门把手上的钥匙开关）";
CM_ SG_ 2332753737 FaultClearCommand_09 "故障清除指令";
CM_ SG_ 2332753738 FireFault_Level1_10 "一级消防故障";
CM_ SG_ 2332753738 FireFault_Level2_10 "二级消防故障";
CM_ SG_ 2332753738 TempState_10 "温感状态";
CM_ SG_ 2332753738 FogState_10 "烟感状态";
CM_ SG_ 2332753738 AerosolState_10 "气溶胶状态";
CM_ SG_ 2332753738 AerosolFaultState_10 "气溶胶故障状态";
CM_ SG_ 2332753738 DoorState_10 "门禁状态";
CM_ SG_ 2332753738 ControlBoxFanState_10 "主控箱风机状态";
CM_ SG_ 2332753738 ControlBoxTempHighWarning_10 "主控箱高温告警";
CM_ SG_ 2332753738 PowerSWState_10 "单柜开关状态（门把手上的钥匙开关）";
CM_ SG_ 2332753738 FaultClearCommand_10 "故障清除指令";
CM_ SG_ 2332753739 FireFault_Level1_11 "一级消防故障";
CM_ SG_ 2332753739 FireFault_Level2_11 "二级消防故障";
CM_ SG_ 2332753739 TempState_11 "温感状态";
CM_ SG_ 2332753739 FogState_11 "烟感状态";
CM_ SG_ 2332753739 AerosolState_11 "气溶胶状态";
CM_ SG_ 2332753739 AerosolFaultState_11 "气溶胶故障状态";
CM_ SG_ 2332753739 DoorState_11 "门禁状态";
CM_ SG_ 2332753739 ControlBoxFanState_11 "主控箱风机状态";
CM_ SG_ 2332753739 ControlBoxTempHighWarning_11 "主控箱高温告警";
CM_ SG_ 2332753739 PowerSWState_11 "单柜开关状态（门把手上的钥匙开关）";
CM_ SG_ 2332753739 FaultClearCommand_11 "故障清除指令";
CM_ SG_ 2332753740 FireFault_Level1_12 "一级消防故障";
CM_ SG_ 2332753740 FireFault_Level2_12 "二级消防故障";
CM_ SG_ 2332753740 TempState_12 "温感状态";
CM_ SG_ 2332753740 FogState_12 "烟感状态";
CM_ SG_ 2332753740 AerosolState_12 "气溶胶状态";
CM_ SG_ 2332753740 AerosolFaultState_12 "气溶胶故障状态";
CM_ SG_ 2332753740 DoorState_12 "门禁状态";
CM_ SG_ 2332753740 ControlBoxFanState_12 "主控箱风机状态";
CM_ SG_ 2332753740 ControlBoxTempHighWarning_12 "主控箱高温告警";
CM_ SG_ 2332753740 PowerSWState_12 "单柜开关状态（门把手上的钥匙开关）";
CM_ SG_ 2332753740 FaultClearCommand_12 "故障清除指令";
CM_ SG_ 2332753741 FireFault_Level1_13 "一级消防故障";
CM_ SG_ 2332753741 FireFault_Level2_13 "二级消防故障";
CM_ SG_ 2332753741 TempState_13 "温感状态";
CM_ SG_ 2332753741 FogState_13 "烟感状态";
CM_ SG_ 2332753741 AerosolState_13 "气溶胶状态";
CM_ SG_ 2332753741 AerosolFaultState_13 "气溶胶故障状态";
CM_ SG_ 2332753741 DoorState_13 "门禁状态";
CM_ SG_ 2332753741 ControlBoxFanState_13 "主控箱风机状态";
CM_ SG_ 2332753741 ControlBoxTempHighWarning_13 "主控箱高温告警";
CM_ SG_ 2332753741 PowerSWState_13 "单柜开关状态（门把手上的钥匙开关）";
CM_ SG_ 2332753741 FaultClearCommand_13 "故障清除指令";
CM_ SG_ 2332753742 FireFault_Level1_14 "一级消防故障";
CM_ SG_ 2332753742 FireFault_Level2_14 "二级消防故障";
CM_ SG_ 2332753742 TempState_14 "温感状态";
CM_ SG_ 2332753742 FogState_14 "烟感状态";
CM_ SG_ 2332753742 AerosolState_14 "气溶胶状态";
CM_ SG_ 2332753742 AerosolFaultState_14 "气溶胶故障状态";
CM_ SG_ 2332753742 DoorState_14 "门禁状态";
CM_ SG_ 2332753742 ControlBoxFanState_14 "主控箱风机状态";
CM_ SG_ 2332753742 ControlBoxTempHighWarning_14 "主控箱高温告警";
CM_ SG_ 2332753742 PowerSWState_14 "单柜开关状态（门把手上的钥匙开关）";
CM_ SG_ 2332753742 FaultClearCommand_14 "故障清除指令";
CM_ SG_ 2332753743 FireFault_Level1_15 "一级消防故障";
CM_ SG_ 2332753743 FireFault_Level2_15 "二级消防故障";
CM_ SG_ 2332753743 TempState_15 "温感状态";
CM_ SG_ 2332753743 FogState_15 "烟感状态";
CM_ SG_ 2332753743 AerosolState_15 "气溶胶状态";
CM_ SG_ 2332753743 AerosolFaultState_15 "气溶胶故障状态";
CM_ SG_ 2332753743 DoorState_15 "门禁状态";
CM_ SG_ 2332753743 ControlBoxFanState_15 "主控箱风机状态";
CM_ SG_ 2332753743 ControlBoxTempHighWarning_15 "主控箱高温告警";
CM_ SG_ 2332753743 PowerSWState_15 "单柜开关状态（门把手上的钥匙开关）";
CM_ SG_ 2332753743 FaultClearCommand_15 "故障清除指令";
CM_ SG_ 2332753744 FireFault_Level1_16 "一级消防故障";
CM_ SG_ 2332753744 FireFault_Level2_16 "二级消防故障";
CM_ SG_ 2332753744 TempState_16 "温感状态";
CM_ SG_ 2332753744 FogState_16 "烟感状态";
CM_ SG_ 2332753744 AerosolState_16 "气溶胶状态";
CM_ SG_ 2332753744 AerosolFaultState_16 "气溶胶故障状态";
CM_ SG_ 2332753744 DoorState_16 "门禁状态";
CM_ SG_ 2332753744 ControlBoxFanState_16 "主控箱风机状态";
CM_ SG_ 2332753744 ControlBoxTempHighWarning_16 "主控箱高温告警";
CM_ SG_ 2332753744 PowerSWState_16 "单柜开关状态（门把手上的钥匙开关）";
CM_ SG_ 2332753744 FaultClearCommand_16 "故障清除指令";
CM_ SG_ 2332753745 FireFault_Level1_17 "一级消防故障";
CM_ SG_ 2332753745 FireFault_Level2_17 "二级消防故障";
CM_ SG_ 2332753745 TempState_17 "温感状态";
CM_ SG_ 2332753745 FogState_17 "烟感状态";
CM_ SG_ 2332753745 AerosolState_17 "气溶胶状态";
CM_ SG_ 2332753745 AerosolFaultState_17 "气溶胶故障状态";
CM_ SG_ 2332753745 DoorState_17 "门禁状态";
CM_ SG_ 2332753745 ControlBoxFanState_17 "主控箱风机状态";
CM_ SG_ 2332753745 ControlBoxTempHighWarning_17 "主控箱高温告警";
CM_ SG_ 2332753745 PowerSWState_17 "单柜开关状态（门把手上的钥匙开关）";
CM_ SG_ 2332753745 FaultClearCommand_17 "故障清除指令";
CM_ SG_ 2332753746 FireFault_Level1_18 "一级消防故障";
CM_ SG_ 2332753746 FireFault_Level2_18 "二级消防故障";
CM_ SG_ 2332753746 TempState_18 "温感状态";
CM_ SG_ 2332753746 FogState_18 "烟感状态";
CM_ SG_ 2332753746 AerosolState_18 "气溶胶状态";
CM_ SG_ 2332753746 AerosolFaultState_18 "气溶胶故障状态";
CM_ SG_ 2332753746 DoorState_18 "门禁状态";
CM_ SG_ 2332753746 ControlBoxFanState_18 "主控箱风机状态";
CM_ SG_ 2332753746 ControlBoxTempHighWarning_18 "主控箱高温告警";
CM_ SG_ 2332753746 PowerSWState_18 "单柜开关状态（门把手上的钥匙开关）";
CM_ SG_ 2332753746 FaultClearCommand_18 "故障清除指令";
CM_ SG_ 2332753747 FireFault_Level1_19 "一级消防故障";
CM_ SG_ 2332753747 FireFault_Level2_19 "二级消防故障";
CM_ SG_ 2332753747 TempState_19 "温感状态";
CM_ SG_ 2332753747 FogState_19 "烟感状态";
CM_ SG_ 2332753747 AerosolState_19 "气溶胶状态";
CM_ SG_ 2332753747 AerosolFaultState_19 "气溶胶故障状态";
CM_ SG_ 2332753747 DoorState_19 "门禁状态";
CM_ SG_ 2332753747 ControlBoxFanState_19 "主控箱风机状态";
CM_ SG_ 2332753747 ControlBoxTempHighWarning_19 "主控箱高温告警";
CM_ SG_ 2332753747 PowerSWState_19 "单柜开关状态（门把手上的钥匙开关）";
CM_ SG_ 2332753747 FaultClearCommand_19 "故障清除指令";
VAL_ 2332688195 B2T_ControlMode_03 0 "关机模式" 1 "制冷模式" 2 "加热模式" 3 "自循环模式" ;
VAL_ 2332688195 TMS_RunState_03 0 "关机模式" 1 "制冷模式" 2 "加热模式" 3 "自循环模式" ;
VAL_ 2332688195 TMS_CommuFault_03 0 "无效" 1 "1级故障" ;
VAL_ 2332688195 TMS_ModeConflict_03 0 "无故障" 1 "故障" ;
VAL_ 2332688195 TMS_MakeBMSStop_03 0 "无故障" 1 "故障" ;
VAL_ 2332688195 TMS_HVRealyState_03 0 "断开状态" 1 "闭合状态" ;
VAL_ 2332688195 TMS_FaultCode_03 0 "无故障" ;
VAL_ 2332688195 TMS_FaultLevel_03 0 "无效" 1 "1级故障" 2 "2级故障" 3 "3级故障" ;
VAL_ 2332688195 B2T_TmptSetPoint_03 255 "Invalid" ;
VAL_ 2332688195 TMS_OutWaterTemp_03 255 "无效" ;
VAL_ 2332688195 TMS_BackWaterTemp_03 255 "无效" ;
VAL_ 2332688195 TMS_EnvTemp_03 255 "无效" ;
VAL_ 2332688195 TMS_RequestPower_03 65535 "无效" ;
VAL_ 2332688195 STMS_ThrmStopReason_03 0 "热管理正常停止" 1 "热管理由于其他模块故障停止" 2 "热管理由于热管理模块故障停止" ;
VAL_ 2332688196 B2T_ControlMode_04 0 "关机模式" 1 "制冷模式" 2 "加热模式" 3 "自循环模式" ;
VAL_ 2332688196 TMS_RunState_04 0 "关机模式" 1 "制冷模式" 2 "加热模式" 3 "自循环模式" ;
VAL_ 2332688196 TMS_CommuFault_04 0 "无效" 1 "1级故障" ;
VAL_ 2332688196 TMS_ModeConflict_04 0 "无故障" 1 "故障" ;
VAL_ 2332688196 TMS_MakeBMSStop_04 0 "无故障" 1 "故障" ;
VAL_ 2332688196 TMS_HVRealyState_04 0 "断开状态" 1 "闭合状态" ;
VAL_ 2332688196 TMS_FaultCode_04 0 "无故障" ;
VAL_ 2332688196 TMS_FaultLevel_04 0 "无效" 1 "1级故障" 2 "2级故障" 3 "3级故障" ;
VAL_ 2332688196 B2T_TmptSetPoint_04 255 "Invalid" ;
VAL_ 2332688196 TMS_OutWaterTemp_04 255 "无效" ;
VAL_ 2332688196 TMS_BackWaterTemp_04 255 "无效" ;
VAL_ 2332688196 TMS_EnvTemp_04 255 "无效" ;
VAL_ 2332688196 TMS_RequestPower_04 65535 "无效" ;
VAL_ 2332688196 STMS_ThrmStopReason_04 0 "热管理正常停止" 1 "热管理由于其他模块故障停止" 2 "热管理由于热管理模块故障停止" ;
VAL_ 2332688197 B2T_ControlMode_05 0 "关机模式" 1 "制冷模式" 2 "加热模式" 3 "自循环模式" ;
VAL_ 2332688197 TMS_RunState_05 0 "关机模式" 1 "制冷模式" 2 "加热模式" 3 "自循环模式" ;
VAL_ 2332688197 TMS_CommuFault_05 0 "无效" 1 "1级故障" ;
VAL_ 2332688197 TMS_ModeConflict_05 0 "无故障" 1 "故障" ;
VAL_ 2332688197 TMS_MakeBMSStop_05 0 "无故障" 1 "故障" ;
VAL_ 2332688197 TMS_HVRealyState_05 0 "断开状态" 1 "闭合状态" ;
VAL_ 2332688197 TMS_FaultCode_05 0 "无故障" ;
VAL_ 2332688197 TMS_FaultLevel_05 0 "无效" 1 "1级故障" 2 "2级故障" 3 "3级故障" ;
VAL_ 2332688197 B2T_TmptSetPoint_05 255 "Invalid" ;
VAL_ 2332688197 TMS_OutWaterTemp_05 255 "无效" ;
VAL_ 2332688197 TMS_BackWaterTemp_05 255 "无效" ;
VAL_ 2332688197 TMS_EnvTemp_05 255 "无效" ;
VAL_ 2332688197 TMS_RequestPower_05 65535 "无效" ;
VAL_ 2332688197 STMS_ThrmStopReason_05 0 "热管理正常停止" 1 "热管理由于其他模块故障停止" 2 "热管理由于热管理模块故障停止" ;
VAL_ 2332688198 B2T_ControlMode_06 0 "关机模式" 1 "制冷模式" 2 "加热模式" 3 "自循环模式" ;
VAL_ 2332688198 TMS_RunState_06 0 "关机模式" 1 "制冷模式" 2 "加热模式" 3 "自循环模式" ;
VAL_ 2332688198 TMS_CommuFault_06 0 "无效" 1 "1级故障" ;
VAL_ 2332688198 TMS_ModeConflict_06 0 "无故障" 1 "故障" ;
VAL_ 2332688198 TMS_MakeBMSStop_06 0 "无故障" 1 "故障" ;
VAL_ 2332688198 TMS_HVRealyState_06 0 "断开状态" 1 "闭合状态" ;
VAL_ 2332688198 TMS_FaultCode_06 0 "无故障" ;
VAL_ 2332688198 TMS_FaultLevel_06 0 "无效" 1 "1级故障" 2 "2级故障" 3 "3级故障" ;
VAL_ 2332688198 B2T_TmptSetPoint_06 255 "Invalid" ;
VAL_ 2332688198 TMS_OutWaterTemp_06 255 "无效" ;
VAL_ 2332688198 TMS_BackWaterTemp_06 255 "无效" ;
VAL_ 2332688198 TMS_EnvTemp_06 255 "无效" ;
VAL_ 2332688198 TMS_RequestPower_06 65535 "无效" ;
VAL_ 2332688198 STMS_ThrmStopReason_06 0 "热管理正常停止" 1 "热管理由于其他模块故障停止" 2 "热管理由于热管理模块故障停止" ;
VAL_ 2332688199 B2T_ControlMode_07 0 "关机模式" 1 "制冷模式" 2 "加热模式" 3 "自循环模式" ;
VAL_ 2332688199 TMS_RunState_07 0 "关机模式" 1 "制冷模式" 2 "加热模式" 3 "自循环模式" ;
VAL_ 2332688199 TMS_CommuFault_07 0 "无效" 1 "1级故障" ;
VAL_ 2332688199 TMS_ModeConflict_07 0 "无故障" 1 "故障" ;
VAL_ 2332688199 TMS_MakeBMSStop_07 0 "无故障" 1 "故障" ;
VAL_ 2332688199 TMS_HVRealyState_07 0 "断开状态" 1 "闭合状态" ;
VAL_ 2332688199 TMS_FaultCode_07 0 "无故障" ;
VAL_ 2332688199 TMS_FaultLevel_07 0 "无效" 1 "1级故障" 2 "2级故障" 3 "3级故障" ;
VAL_ 2332688199 B2T_TmptSetPoint_07 255 "Invalid" ;
VAL_ 2332688199 TMS_OutWaterTemp_07 255 "无效" ;
VAL_ 2332688199 TMS_BackWaterTemp_07 255 "无效" ;
VAL_ 2332688199 TMS_EnvTemp_07 255 "无效" ;
VAL_ 2332688199 TMS_RequestPower_07 65535 "无效" ;
VAL_ 2332688199 STMS_ThrmStopReason_07 0 "热管理正常停止" 1 "热管理由于其他模块故障停止" 2 "热管理由于热管理模块故障停止" ;
VAL_ 2332688200 B2T_ControlMode_08 0 "关机模式" 1 "制冷模式" 2 "加热模式" 3 "自循环模式" ;
VAL_ 2332688200 TMS_RunState_08 0 "关机模式" 1 "制冷模式" 2 "加热模式" 3 "自循环模式" ;
VAL_ 2332688200 TMS_CommuFault_08 0 "无效" 1 "1级故障" ;
VAL_ 2332688200 TMS_ModeConflict_08 0 "无故障" 1 "故障" ;
VAL_ 2332688200 TMS_MakeBMSStop_08 0 "无故障" 1 "故障" ;
VAL_ 2332688200 TMS_HVRealyState_08 0 "断开状态" 1 "闭合状态" ;
VAL_ 2332688200 TMS_FaultCode_08 0 "无故障" ;
VAL_ 2332688200 TMS_FaultLevel_08 0 "无效" 1 "1级故障" 2 "2级故障" 3 "3级故障" ;
VAL_ 2332688200 B2T_TmptSetPoint_08 255 "Invalid" ;
VAL_ 2332688200 TMS_OutWaterTemp_08 255 "无效" ;
VAL_ 2332688200 TMS_BackWaterTemp_08 255 "无效" ;
VAL_ 2332688200 TMS_EnvTemp_08 255 "无效" ;
VAL_ 2332688200 TMS_RequestPower_08 65535 "无效" ;
VAL_ 2332688200 STMS_ThrmStopReason_08 0 "热管理正常停止" 1 "热管理由于其他模块故障停止" 2 "热管理由于热管理模块故障停止" ;
VAL_ 2332688201 B2T_ControlMode_09 0 "关机模式" 1 "制冷模式" 2 "加热模式" 3 "自循环模式" ;
VAL_ 2332688201 TMS_RunState_09 0 "关机模式" 1 "制冷模式" 2 "加热模式" 3 "自循环模式" ;
VAL_ 2332688201 TMS_CommuFault_09 0 "无效" 1 "1级故障" ;
VAL_ 2332688201 TMS_ModeConflict_09 0 "无故障" 1 "故障" ;
VAL_ 2332688201 TMS_MakeBMSStop_09 0 "无故障" 1 "故障" ;
VAL_ 2332688201 TMS_HVRealyState_09 0 "断开状态" 1 "闭合状态" ;
VAL_ 2332688201 TMS_FaultCode_09 0 "无故障" ;
VAL_ 2332688201 TMS_FaultLevel_09 0 "无效" 1 "1级故障" 2 "2级故障" 3 "3级故障" ;
VAL_ 2332688201 B2T_TmptSetPoint_09 255 "Invalid" ;
VAL_ 2332688201 TMS_OutWaterTemp_09 255 "无效" ;
VAL_ 2332688201 TMS_BackWaterTemp_09 255 "无效" ;
VAL_ 2332688201 TMS_EnvTemp_09 255 "无效" ;
VAL_ 2332688201 TMS_RequestPower_09 65535 "无效" ;
VAL_ 2332688201 STMS_ThrmStopReason_09 0 "热管理正常停止" 1 "热管理由于其他模块故障停止" 2 "热管理由于热管理模块故障停止" ;
VAL_ 2332688202 B2T_ControlMode_10 0 "关机模式" 1 "制冷模式" 2 "加热模式" 3 "自循环模式" ;
VAL_ 2332688202 TMS_RunState_10 0 "关机模式" 1 "制冷模式" 2 "加热模式" 3 "自循环模式" ;
VAL_ 2332688202 TMS_CommuFault_10 0 "无效" 1 "1级故障" ;
VAL_ 2332688202 TMS_ModeConflict_10 0 "无故障" 1 "故障" ;
VAL_ 2332688202 TMS_MakeBMSStop_10 0 "无故障" 1 "故障" ;
VAL_ 2332688202 TMS_HVRealyState_10 0 "断开状态" 1 "闭合状态" ;
VAL_ 2332688202 TMS_FaultCode_10 0 "无故障" ;
VAL_ 2332688202 TMS_FaultLevel_10 0 "无效" 1 "1级故障" 2 "2级故障" 3 "3级故障" ;
VAL_ 2332688202 B2T_TmptSetPoint_10 255 "Invalid" ;
VAL_ 2332688202 TMS_OutWaterTemp_10 255 "无效" ;
VAL_ 2332688202 TMS_BackWaterTemp_10 255 "无效" ;
VAL_ 2332688202 TMS_EnvTemp_10 255 "无效" ;
VAL_ 2332688202 TMS_RequestPower_10 65535 "无效" ;
VAL_ 2332688202 STMS_ThrmStopReason_10 0 "热管理正常停止" 1 "热管理由于其他模块故障停止" 2 "热管理由于热管理模块故障停止" ;
VAL_ 2332688203 B2T_ControlMode_11 0 "关机模式" 1 "制冷模式" 2 "加热模式" 3 "自循环模式" ;
VAL_ 2332688203 TMS_RunState_11 0 "关机模式" 1 "制冷模式" 2 "加热模式" 3 "自循环模式" ;
VAL_ 2332688203 TMS_CommuFault_11 0 "无效" 1 "1级故障" ;
VAL_ 2332688203 TMS_ModeConflict_11 0 "无故障" 1 "故障" ;
VAL_ 2332688203 TMS_MakeBMSStop_11 0 "无故障" 1 "故障" ;
VAL_ 2332688203 TMS_HVRealyState_11 0 "断开状态" 1 "闭合状态" ;
VAL_ 2332688203 TMS_FaultCode_11 0 "无故障" ;
VAL_ 2332688203 TMS_FaultLevel_11 0 "无效" 1 "1级故障" 2 "2级故障" 3 "3级故障" ;
VAL_ 2332688203 B2T_TmptSetPoint_11 255 "Invalid" ;
VAL_ 2332688203 TMS_OutWaterTemp_11 255 "无效" ;
VAL_ 2332688203 TMS_BackWaterTemp_11 255 "无效" ;
VAL_ 2332688203 TMS_EnvTemp_11 255 "无效" ;
VAL_ 2332688203 TMS_RequestPower_11 65535 "无效" ;
VAL_ 2332688203 STMS_ThrmStopReason_11 0 "热管理正常停止" 1 "热管理由于其他模块故障停止" 2 "热管理由于热管理模块故障停止" ;
VAL_ 2332688204 B2T_ControlMode_12 0 "关机模式" 1 "制冷模式" 2 "加热模式" 3 "自循环模式" ;
VAL_ 2332688204 TMS_RunState_12 0 "关机模式" 1 "制冷模式" 2 "加热模式" 3 "自循环模式" ;
VAL_ 2332688204 TMS_CommuFault_12 0 "无效" 1 "1级故障" ;
VAL_ 2332688204 TMS_ModeConflict_12 0 "无故障" 1 "故障" ;
VAL_ 2332688204 TMS_MakeBMSStop_12 0 "无故障" 1 "故障" ;
VAL_ 2332688204 TMS_HVRealyState_12 0 "断开状态" 1 "闭合状态" ;
VAL_ 2332688204 TMS_FaultCode_12 0 "无故障" ;
VAL_ 2332688204 TMS_FaultLevel_12 0 "无效" 1 "1级故障" 2 "2级故障" 3 "3级故障" ;
VAL_ 2332688204 B2T_TmptSetPoint_12 255 "Invalid" ;
VAL_ 2332688204 TMS_OutWaterTemp_12 255 "无效" ;
VAL_ 2332688204 TMS_BackWaterTemp_12 255 "无效" ;
VAL_ 2332688204 TMS_EnvTemp_12 255 "无效" ;
VAL_ 2332688204 TMS_RequestPower_12 65535 "无效" ;
VAL_ 2332688204 STMS_ThrmStopReason_12 0 "热管理正常停止" 1 "热管理由于其他模块故障停止" 2 "热管理由于热管理模块故障停止" ;
VAL_ 2332688205 B2T_ControlMode_13 0 "关机模式" 1 "制冷模式" 2 "加热模式" 3 "自循环模式" ;
VAL_ 2332688205 TMS_RunState_13 0 "关机模式" 1 "制冷模式" 2 "加热模式" 3 "自循环模式" ;
VAL_ 2332688205 TMS_CommuFault_13 0 "无效" 1 "1级故障" ;
VAL_ 2332688205 TMS_ModeConflict_13 0 "无故障" 1 "故障" ;
VAL_ 2332688205 TMS_MakeBMSStop_13 0 "无故障" 1 "故障" ;
VAL_ 2332688205 TMS_HVRealyState_13 0 "断开状态" 1 "闭合状态" ;
VAL_ 2332688205 TMS_FaultCode_13 0 "无故障" ;
VAL_ 2332688205 TMS_FaultLevel_13 0 "无效" 1 "1级故障" 2 "2级故障" 3 "3级故障" ;
VAL_ 2332688205 B2T_TmptSetPoint_13 255 "Invalid" ;
VAL_ 2332688205 TMS_OutWaterTemp_13 255 "无效" ;
VAL_ 2332688205 TMS_BackWaterTemp_13 255 "无效" ;
VAL_ 2332688205 TMS_EnvTemp_13 255 "无效" ;
VAL_ 2332688205 TMS_RequestPower_13 65535 "无效" ;
VAL_ 2332688205 STMS_ThrmStopReason_13 0 "热管理正常停止" 1 "热管理由于其他模块故障停止" 2 "热管理由于热管理模块故障停止" ;
VAL_ 2332688206 B2T_ControlMode_14 0 "关机模式" 1 "制冷模式" 2 "加热模式" 3 "自循环模式" ;
VAL_ 2332688206 TMS_RunState_14 0 "关机模式" 1 "制冷模式" 2 "加热模式" 3 "自循环模式" ;
VAL_ 2332688206 TMS_CommuFault_14 0 "无效" 1 "1级故障" ;
VAL_ 2332688206 TMS_ModeConflict_14 0 "无故障" 1 "故障" ;
VAL_ 2332688206 TMS_MakeBMSStop_14 0 "无故障" 1 "故障" ;
VAL_ 2332688206 TMS_HVRealyState_14 0 "断开状态" 1 "闭合状态" ;
VAL_ 2332688206 TMS_FaultCode_14 0 "无故障" ;
VAL_ 2332688206 TMS_FaultLevel_14 0 "无效" 1 "1级故障" 2 "2级故障" 3 "3级故障" ;
VAL_ 2332688206 B2T_TmptSetPoint_14 255 "Invalid" ;
VAL_ 2332688206 TMS_OutWaterTemp_14 255 "无效" ;
VAL_ 2332688206 TMS_BackWaterTemp_14 255 "无效" ;
VAL_ 2332688206 TMS_EnvTemp_14 255 "无效" ;
VAL_ 2332688206 TMS_RequestPower_14 65535 "无效" ;
VAL_ 2332688206 STMS_ThrmStopReason_14 0 "热管理正常停止" 1 "热管理由于其他模块故障停止" 2 "热管理由于热管理模块故障停止" ;
VAL_ 2332688207 B2T_ControlMode_15 0 "关机模式" 1 "制冷模式" 2 "加热模式" 3 "自循环模式" ;
VAL_ 2332688207 TMS_RunState_15 0 "关机模式" 1 "制冷模式" 2 "加热模式" 3 "自循环模式" ;
VAL_ 2332688207 TMS_CommuFault_15 0 "无效" 1 "1级故障" ;
VAL_ 2332688207 TMS_ModeConflict_15 0 "无故障" 1 "故障" ;
VAL_ 2332688207 TMS_MakeBMSStop_15 0 "无故障" 1 "故障" ;
VAL_ 2332688207 TMS_HVRealyState_15 0 "断开状态" 1 "闭合状态" ;
VAL_ 2332688207 TMS_FaultCode_15 0 "无故障" ;
VAL_ 2332688207 TMS_FaultLevel_15 0 "无效" 1 "1级故障" 2 "2级故障" 3 "3级故障" ;
VAL_ 2332688207 B2T_TmptSetPoint_15 255 "Invalid" ;
VAL_ 2332688207 TMS_OutWaterTemp_15 255 "无效" ;
VAL_ 2332688207 TMS_BackWaterTemp_15 255 "无效" ;
VAL_ 2332688207 TMS_EnvTemp_15 255 "无效" ;
VAL_ 2332688207 TMS_RequestPower_15 65535 "无效" ;
VAL_ 2332688207 STMS_ThrmStopReason_15 0 "热管理正常停止" 1 "热管理由于其他模块故障停止" 2 "热管理由于热管理模块故障停止" ;
VAL_ 2332688208 B2T_ControlMode_16 0 "关机模式" 1 "制冷模式" 2 "加热模式" 3 "自循环模式" ;
VAL_ 2332688208 TMS_RunState_16 0 "关机模式" 1 "制冷模式" 2 "加热模式" 3 "自循环模式" ;
VAL_ 2332688208 TMS_CommuFault_16 0 "无效" 1 "1级故障" ;
VAL_ 2332688208 TMS_ModeConflict_16 0 "无故障" 1 "故障" ;
VAL_ 2332688208 TMS_MakeBMSStop_16 0 "无故障" 1 "故障" ;
VAL_ 2332688208 TMS_HVRealyState_16 0 "断开状态" 1 "闭合状态" ;
VAL_ 2332688208 TMS_FaultCode_16 0 "无故障" ;
VAL_ 2332688208 TMS_FaultLevel_16 0 "无效" 1 "1级故障" 2 "2级故障" 3 "3级故障" ;
VAL_ 2332688208 B2T_TmptSetPoint_16 255 "Invalid" ;
VAL_ 2332688208 TMS_OutWaterTemp_16 255 "无效" ;
VAL_ 2332688208 TMS_BackWaterTemp_16 255 "无效" ;
VAL_ 2332688208 TMS_EnvTemp_16 255 "无效" ;
VAL_ 2332688208 TMS_RequestPower_16 65535 "无效" ;
VAL_ 2332688208 STMS_ThrmStopReason_16 0 "热管理正常停止" 1 "热管理由于其他模块故障停止" 2 "热管理由于热管理模块故障停止" ;
VAL_ 2332688209 B2T_ControlMode_17 0 "关机模式" 1 "制冷模式" 2 "加热模式" 3 "自循环模式" ;
VAL_ 2332688209 TMS_RunState_17 0 "关机模式" 1 "制冷模式" 2 "加热模式" 3 "自循环模式" ;
VAL_ 2332688209 TMS_CommuFault_17 0 "无效" 1 "1级故障" ;
VAL_ 2332688209 TMS_ModeConflict_17 0 "无故障" 1 "故障" ;
VAL_ 2332688209 TMS_MakeBMSStop_17 0 "无故障" 1 "故障" ;
VAL_ 2332688209 TMS_HVRealyState_17 0 "断开状态" 1 "闭合状态" ;
VAL_ 2332688209 TMS_FaultCode_17 0 "无故障" ;
VAL_ 2332688209 TMS_FaultLevel_17 0 "无效" 1 "1级故障" 2 "2级故障" 3 "3级故障" ;
VAL_ 2332688209 B2T_TmptSetPoint_17 255 "Invalid" ;
VAL_ 2332688209 TMS_OutWaterTemp_17 255 "无效" ;
VAL_ 2332688209 TMS_BackWaterTemp_17 255 "无效" ;
VAL_ 2332688209 TMS_EnvTemp_17 255 "无效" ;
VAL_ 2332688209 TMS_RequestPower_17 65535 "无效" ;
VAL_ 2332688209 STMS_ThrmStopReason_17 0 "热管理正常停止" 1 "热管理由于其他模块故障停止" 2 "热管理由于热管理模块故障停止" ;
VAL_ 2332688210 B2T_ControlMode_18 0 "关机模式" 1 "制冷模式" 2 "加热模式" 3 "自循环模式" ;
VAL_ 2332688210 TMS_RunState_18 0 "关机模式" 1 "制冷模式" 2 "加热模式" 3 "自循环模式" ;
VAL_ 2332688210 TMS_CommuFault_18 0 "无效" 1 "1级故障" ;
VAL_ 2332688210 TMS_ModeConflict_18 0 "无故障" 1 "故障" ;
VAL_ 2332688210 TMS_MakeBMSStop_18 0 "无故障" 1 "故障" ;
VAL_ 2332688210 TMS_HVRealyState_18 0 "断开状态" 1 "闭合状态" ;
VAL_ 2332688210 TMS_FaultCode_18 0 "无故障" ;
VAL_ 2332688210 TMS_FaultLevel_18 0 "无效" 1 "1级故障" 2 "2级故障" 3 "3级故障" ;
VAL_ 2332688210 B2T_TmptSetPoint_18 255 "Invalid" ;
VAL_ 2332688210 TMS_OutWaterTemp_18 255 "无效" ;
VAL_ 2332688210 TMS_BackWaterTemp_18 255 "无效" ;
VAL_ 2332688210 TMS_EnvTemp_18 255 "无效" ;
VAL_ 2332688210 TMS_RequestPower_18 65535 "无效" ;
VAL_ 2332688210 STMS_ThrmStopReason_18 0 "热管理正常停止" 1 "热管理由于其他模块故障停止" 2 "热管理由于热管理模块故障停止" ;
VAL_ 2332688211 B2T_ControlMode_19 0 "关机模式" 1 "制冷模式" 2 "加热模式" 3 "自循环模式" ;
VAL_ 2332688211 TMS_RunState_19 0 "关机模式" 1 "制冷模式" 2 "加热模式" 3 "自循环模式" ;
VAL_ 2332688211 TMS_CommuFault_19 0 "无效" 1 "1级故障" ;
VAL_ 2332688211 TMS_ModeConflict_19 0 "无故障" 1 "故障" ;
VAL_ 2332688211 TMS_MakeBMSStop_19 0 "无故障" 1 "故障" ;
VAL_ 2332688211 TMS_HVRealyState_19 0 "断开状态" 1 "闭合状态" ;
VAL_ 2332688211 TMS_FaultCode_19 0 "无故障" ;
VAL_ 2332688211 TMS_FaultLevel_19 0 "无效" 1 "1级故障" 2 "2级故障" 3 "3级故障" ;
VAL_ 2332688211 B2T_TmptSetPoint_19 255 "Invalid" ;
VAL_ 2332688211 TMS_OutWaterTemp_19 255 "无效" ;
VAL_ 2332688211 TMS_BackWaterTemp_19 255 "无效" ;
VAL_ 2332688211 TMS_EnvTemp_19 255 "无效" ;
VAL_ 2332688211 TMS_RequestPower_19 65535 "无效" ;
VAL_ 2332688211 STMS_ThrmStopReason_19 0 "热管理正常停止" 1 "热管理由于其他模块故障停止" 2 "热管理由于热管理模块故障停止" ;
VAL_ 2332688212 B2T_ControlMode_20 0 "关机模式" 1 "制冷模式" 2 "加热模式" 3 "自循环模式" ;
VAL_ 2332688212 TMS_RunState_20 0 "关机模式" 1 "制冷模式" 2 "加热模式" 3 "自循环模式" ;
VAL_ 2332688212 TMS_CommuFault_20 0 "无效" 1 "1级故障" ;
VAL_ 2332688212 TMS_ModeConflict_20 0 "无故障" 1 "故障" ;
VAL_ 2332688212 TMS_MakeBMSStop_20 0 "无故障" 1 "故障" ;
VAL_ 2332688212 TMS_HVRealyState_20 0 "断开状态" 1 "闭合状态" ;
VAL_ 2332688212 TMS_FaultCode_20 0 "无故障" ;
VAL_ 2332688212 TMS_FaultLevel_20 0 "无效" 1 "1级故障" 2 "2级故障" 3 "3级故障" ;
VAL_ 2332688212 B2T_TmptSetPoint_20 255 "Invalid" ;
VAL_ 2332688212 TMS_OutWaterTemp_20 255 "无效" ;
VAL_ 2332688212 TMS_BackWaterTemp_20 255 "无效" ;
VAL_ 2332688212 TMS_EnvTemp_20 255 "无效" ;
VAL_ 2332688212 TMS_RequestPower_20 65535 "无效" ;
VAL_ 2332688212 STMS_ThrmStopReason_20 0 "热管理正常停止" 1 "热管理由于其他模块故障停止" 2 "热管理由于热管理模块故障停止" ;
VAL_ 2332688213 B2T_ControlMode_21 0 "关机模式" 1 "制冷模式" 2 "加热模式" 3 "自循环模式" ;
VAL_ 2332688213 TMS_RunState_21 0 "关机模式" 1 "制冷模式" 2 "加热模式" 3 "自循环模式" ;
VAL_ 2332688213 TMS_CommuFault_21 0 "无效" 1 "1级故障" ;
VAL_ 2332688213 TMS_ModeConflict_21 0 "无故障" 1 "故障" ;
VAL_ 2332688213 TMS_MakeBMSStop_21 0 "无故障" 1 "故障" ;
VAL_ 2332688213 TMS_HVRealyState_21 0 "断开状态" 1 "闭合状态" ;
VAL_ 2332688213 TMS_FaultCode_21 0 "无故障" ;
VAL_ 2332688213 TMS_FaultLevel_21 0 "无效" 1 "1级故障" 2 "2级故障" 3 "3级故障" ;
VAL_ 2332688213 B2T_TmptSetPoint_21 255 "Invalid" ;
VAL_ 2332688213 TMS_OutWaterTemp_21 255 "无效" ;
VAL_ 2332688213 TMS_BackWaterTemp_21 255 "无效" ;
VAL_ 2332688213 TMS_EnvTemp_21 255 "无效" ;
VAL_ 2332688213 TMS_RequestPower_21 65535 "无效" ;
VAL_ 2332688213 STMS_ThrmStopReason_21 0 "热管理正常停止" 1 "热管理由于其他模块故障停止" 2 "热管理由于热管理模块故障停止" ;
VAL_ 2332688214 B2T_ControlMode_22 0 "关机模式" 1 "制冷模式" 2 "加热模式" 3 "自循环模式" ;
VAL_ 2332688214 TMS_RunState_22 0 "关机模式" 1 "制冷模式" 2 "加热模式" 3 "自循环模式" ;
VAL_ 2332688214 TMS_CommuFault_22 0 "无效" 1 "1级故障" ;
VAL_ 2332688214 TMS_ModeConflict_22 0 "无故障" 1 "故障" ;
VAL_ 2332688214 TMS_MakeBMSStop_22 0 "无故障" 1 "故障" ;
VAL_ 2332688214 TMS_HVRealyState_22 0 "断开状态" 1 "闭合状态" ;
VAL_ 2332688214 TMS_FaultCode_22 0 "无故障" ;
VAL_ 2332688214 TMS_FaultLevel_22 0 "无效" 1 "1级故障" 2 "2级故障" 3 "3级故障" ;
VAL_ 2332688214 B2T_TmptSetPoint_22 255 "Invalid" ;
VAL_ 2332688214 TMS_OutWaterTemp_22 255 "无效" ;
VAL_ 2332688214 TMS_BackWaterTemp_22 255 "无效" ;
VAL_ 2332688214 TMS_EnvTemp_22 255 "无效" ;
VAL_ 2332688214 TMS_RequestPower_22 65535 "无效" ;
VAL_ 2332688214 STMS_ThrmStopReason_22 0 "热管理正常停止" 1 "热管理由于其他模块故障停止" 2 "热管理由于热管理模块故障停止" ;
VAL_ 2332688215 B2T_ControlMode_23 0 "关机模式" 1 "制冷模式" 2 "加热模式" 3 "自循环模式" ;
VAL_ 2332688215 TMS_RunState_23 0 "关机模式" 1 "制冷模式" 2 "加热模式" 3 "自循环模式" ;
VAL_ 2332688215 TMS_CommuFault_23 0 "无效" 1 "1级故障" ;
VAL_ 2332688215 TMS_ModeConflict_23 0 "无故障" 1 "故障" ;
VAL_ 2332688215 TMS_MakeBMSStop_23 0 "无故障" 1 "故障" ;
VAL_ 2332688215 TMS_HVRealyState_23 0 "断开状态" 1 "闭合状态" ;
VAL_ 2332688215 TMS_FaultCode_23 0 "无故障" ;
VAL_ 2332688215 TMS_FaultLevel_23 0 "无效" 1 "1级故障" 2 "2级故障" 3 "3级故障" ;
VAL_ 2332688215 B2T_TmptSetPoint_23 255 "Invalid" ;
VAL_ 2332688215 TMS_OutWaterTemp_23 255 "无效" ;
VAL_ 2332688215 TMS_BackWaterTemp_23 255 "无效" ;
VAL_ 2332688215 TMS_EnvTemp_23 255 "无效" ;
VAL_ 2332688215 TMS_RequestPower_23 65535 "无效" ;
VAL_ 2332688215 STMS_ThrmStopReason_23 0 "热管理正常停止" 1 "热管理由于其他模块故障停止" 2 "热管理由于热管理模块故障停止" ;
VAL_ 2332688216 B2T_ControlMode_24 0 "关机模式" 1 "制冷模式" 2 "加热模式" 3 "自循环模式" ;
VAL_ 2332688216 TMS_RunState_24 0 "关机模式" 1 "制冷模式" 2 "加热模式" 3 "自循环模式" ;
VAL_ 2332688216 TMS_CommuFault_24 0 "无效" 1 "1级故障" ;
VAL_ 2332688216 TMS_ModeConflict_24 0 "无故障" 1 "故障" ;
VAL_ 2332688216 TMS_MakeBMSStop_24 0 "无故障" 1 "故障" ;
VAL_ 2332688216 TMS_HVRealyState_24 0 "断开状态" 1 "闭合状态" ;
VAL_ 2332688216 TMS_FaultCode_24 0 "无故障" ;
VAL_ 2332688216 TMS_FaultLevel_24 0 "无效" 1 "1级故障" 2 "2级故障" 3 "3级故障" ;
VAL_ 2332688216 B2T_TmptSetPoint_24 255 "Invalid" ;
VAL_ 2332688216 TMS_OutWaterTemp_24 255 "无效" ;
VAL_ 2332688216 TMS_BackWaterTemp_24 255 "无效" ;
VAL_ 2332688216 TMS_EnvTemp_24 255 "无效" ;
VAL_ 2332688216 TMS_RequestPower_24 65535 "无效" ;
VAL_ 2332688216 STMS_ThrmStopReason_24 0 "热管理正常停止" 1 "热管理由于其他模块故障停止" 2 "热管理由于热管理模块故障停止" ;
VAL_ 2332688217 B2T_ControlMode_25 0 "关机模式" 1 "制冷模式" 2 "加热模式" 3 "自循环模式" ;
VAL_ 2332688217 TMS_RunState_25 0 "关机模式" 1 "制冷模式" 2 "加热模式" 3 "自循环模式" ;
VAL_ 2332688217 TMS_CommuFault_25 0 "无效" 1 "1级故障" ;
VAL_ 2332688217 TMS_ModeConflict_25 0 "无故障" 1 "故障" ;
VAL_ 2332688217 TMS_MakeBMSStop_25 0 "无故障" 1 "故障" ;
VAL_ 2332688217 TMS_HVRealyState_25 0 "断开状态" 1 "闭合状态" ;
VAL_ 2332688217 TMS_FaultCode_25 0 "无故障" ;
VAL_ 2332688217 TMS_FaultLevel_25 0 "无效" 1 "1级故障" 2 "2级故障" 3 "3级故障" ;
VAL_ 2332688217 B2T_TmptSetPoint_25 255 "Invalid" ;
VAL_ 2332688217 TMS_OutWaterTemp_25 255 "无效" ;
VAL_ 2332688217 TMS_BackWaterTemp_25 255 "无效" ;
VAL_ 2332688217 TMS_EnvTemp_25 255 "无效" ;
VAL_ 2332688217 TMS_RequestPower_25 65535 "无效" ;
VAL_ 2332688217 STMS_ThrmStopReason_25 0 "热管理正常停止" 1 "热管理由于其他模块故障停止" 2 "热管理由于热管理模块故障停止" ;
VAL_ 2332688218 B2T_ControlMode_26 0 "关机模式" 1 "制冷模式" 2 "加热模式" 3 "自循环模式" ;
VAL_ 2332688218 TMS_RunState_26 0 "关机模式" 1 "制冷模式" 2 "加热模式" 3 "自循环模式" ;
VAL_ 2332688218 TMS_CommuFault_26 0 "无效" 1 "1级故障" ;
VAL_ 2332688218 TMS_ModeConflict_26 0 "无故障" 1 "故障" ;
VAL_ 2332688218 TMS_MakeBMSStop_26 0 "无故障" 1 "故障" ;
VAL_ 2332688218 TMS_HVRealyState_26 0 "断开状态" 1 "闭合状态" ;
VAL_ 2332688218 TMS_FaultCode_26 0 "无故障" ;
VAL_ 2332688218 TMS_FaultLevel_26 0 "无效" 1 "1级故障" 2 "2级故障" 3 "3级故障" ;
VAL_ 2332688218 B2T_TmptSetPoint_26 255 "Invalid" ;
VAL_ 2332688218 TMS_OutWaterTemp_26 255 "无效" ;
VAL_ 2332688218 TMS_BackWaterTemp_26 255 "无效" ;
VAL_ 2332688218 TMS_EnvTemp_26 255 "无效" ;
VAL_ 2332688218 TMS_RequestPower_26 65535 "无效" ;
VAL_ 2332688218 STMS_ThrmStopReason_26 0 "热管理正常停止" 1 "热管理由于其他模块故障停止" 2 "热管理由于热管理模块故障停止" ;
VAL_ 2332688219 B2T_ControlMode_27 0 "关机模式" 1 "制冷模式" 2 "加热模式" 3 "自循环模式" ;
VAL_ 2332688219 TMS_RunState_27 0 "关机模式" 1 "制冷模式" 2 "加热模式" 3 "自循环模式" ;
VAL_ 2332688219 TMS_CommuFault_27 0 "无效" 1 "1级故障" ;
VAL_ 2332688219 TMS_ModeConflict_27 0 "无故障" 1 "故障" ;
VAL_ 2332688219 TMS_MakeBMSStop_27 0 "无故障" 1 "故障" ;
VAL_ 2332688219 TMS_HVRealyState_27 0 "断开状态" 1 "闭合状态" ;
VAL_ 2332688219 TMS_FaultCode_27 0 "无故障" ;
VAL_ 2332688219 TMS_FaultLevel_27 0 "无效" 1 "1级故障" 2 "2级故障" 3 "3级故障" ;
VAL_ 2332688219 B2T_TmptSetPoint_27 255 "Invalid" ;
VAL_ 2332688219 TMS_OutWaterTemp_27 255 "无效" ;
VAL_ 2332688219 TMS_BackWaterTemp_27 255 "无效" ;
VAL_ 2332688219 TMS_EnvTemp_27 255 "无效" ;
VAL_ 2332688219 TMS_RequestPower_27 65535 "无效" ;
VAL_ 2332688219 STMS_ThrmStopReason_27 0 "热管理正常停止" 1 "热管理由于其他模块故障停止" 2 "热管理由于热管理模块故障停止" ;
VAL_ 2332688220 B2T_ControlMode_28 0 "关机模式" 1 "制冷模式" 2 "加热模式" 3 "自循环模式" ;
VAL_ 2332688220 TMS_RunState_28 0 "关机模式" 1 "制冷模式" 2 "加热模式" 3 "自循环模式" ;
VAL_ 2332688220 TMS_CommuFault_28 0 "无效" 1 "1级故障" ;
VAL_ 2332688220 TMS_ModeConflict_28 0 "无故障" 1 "故障" ;
VAL_ 2332688220 TMS_MakeBMSStop_28 0 "无故障" 1 "故障" ;
VAL_ 2332688220 TMS_HVRealyState_28 0 "断开状态" 1 "闭合状态" ;
VAL_ 2332688220 TMS_FaultCode_28 0 "无故障" ;
VAL_ 2332688220 TMS_FaultLevel_28 0 "无效" 1 "1级故障" 2 "2级故障" 3 "3级故障" ;
VAL_ 2332688220 B2T_TmptSetPoint_28 255 "Invalid" ;
VAL_ 2332688220 TMS_OutWaterTemp_28 255 "无效" ;
VAL_ 2332688220 TMS_BackWaterTemp_28 255 "无效" ;
VAL_ 2332688220 TMS_EnvTemp_28 255 "无效" ;
VAL_ 2332688220 TMS_RequestPower_28 65535 "无效" ;
VAL_ 2332688220 STMS_ThrmStopReason_28 0 "热管理正常停止" 1 "热管理由于其他模块故障停止" 2 "热管理由于热管理模块故障停止" ;
VAL_ 2332688221 B2T_ControlMode_29 0 "关机模式" 1 "制冷模式" 2 "加热模式" 3 "自循环模式" ;
VAL_ 2332688221 TMS_RunState_29 0 "关机模式" 1 "制冷模式" 2 "加热模式" 3 "自循环模式" ;
VAL_ 2332688221 TMS_CommuFault_29 0 "无效" 1 "1级故障" ;
VAL_ 2332688221 TMS_ModeConflict_29 0 "无故障" 1 "故障" ;
VAL_ 2332688221 TMS_MakeBMSStop_29 0 "无故障" 1 "故障" ;
VAL_ 2332688221 TMS_HVRealyState_29 0 "断开状态" 1 "闭合状态" ;
VAL_ 2332688221 TMS_FaultCode_29 0 "无故障" ;
VAL_ 2332688221 TMS_FaultLevel_29 0 "无效" 1 "1级故障" 2 "2级故障" 3 "3级故障" ;
VAL_ 2332688221 B2T_TmptSetPoint_29 255 "Invalid" ;
VAL_ 2332688221 TMS_OutWaterTemp_29 255 "无效" ;
VAL_ 2332688221 TMS_BackWaterTemp_29 255 "无效" ;
VAL_ 2332688221 TMS_EnvTemp_29 255 "无效" ;
VAL_ 2332688221 TMS_RequestPower_29 65535 "无效" ;
VAL_ 2332688221 STMS_ThrmStopReason_29 0 "热管理正常停止" 1 "热管理由于其他模块故障停止" 2 "热管理由于热管理模块故障停止" ;
VAL_ 2332688222 B2T_ControlMode_30 0 "关机模式" 1 "制冷模式" 2 "加热模式" 3 "自循环模式" ;
VAL_ 2332688222 TMS_RunState_30 0 "关机模式" 1 "制冷模式" 2 "加热模式" 3 "自循环模式" ;
VAL_ 2332688222 TMS_CommuFault_30 0 "无效" 1 "1级故障" ;
VAL_ 2332688222 TMS_ModeConflict_30 0 "无故障" 1 "故障" ;
VAL_ 2332688222 TMS_MakeBMSStop_30 0 "无故障" 1 "故障" ;
VAL_ 2332688222 TMS_HVRealyState_30 0 "断开状态" 1 "闭合状态" ;
VAL_ 2332688222 TMS_FaultCode_30 0 "无故障" ;
VAL_ 2332688222 TMS_FaultLevel_30 0 "无效" 1 "1级故障" 2 "2级故障" 3 "3级故障" ;
VAL_ 2332688222 B2T_TmptSetPoint_30 255 "Invalid" ;
VAL_ 2332688222 TMS_OutWaterTemp_30 255 "无效" ;
VAL_ 2332688222 TMS_BackWaterTemp_30 255 "无效" ;
VAL_ 2332688222 TMS_EnvTemp_30 255 "无效" ;
VAL_ 2332688222 TMS_RequestPower_30 65535 "无效" ;
VAL_ 2332688222 STMS_ThrmStopReason_30 0 "热管理正常停止" 1 "热管理由于其他模块故障停止" 2 "热管理由于热管理模块故障停止" ;
VAL_ 2332688223 B2T_ControlMode_31 0 "关机模式" 1 "制冷模式" 2 "加热模式" 3 "自循环模式" ;
VAL_ 2332688223 TMS_RunState_31 0 "关机模式" 1 "制冷模式" 2 "加热模式" 3 "自循环模式" ;
VAL_ 2332688223 TMS_CommuFault_31 0 "无效" 1 "1级故障" ;
VAL_ 2332688223 TMS_ModeConflict_31 0 "无故障" 1 "故障" ;
VAL_ 2332688223 TMS_MakeBMSStop_31 0 "无故障" 1 "故障" ;
VAL_ 2332688223 TMS_HVRealyState_31 0 "断开状态" 1 "闭合状态" ;
VAL_ 2332688223 TMS_FaultCode_31 0 "无故障" ;
VAL_ 2332688223 TMS_FaultLevel_31 0 "无效" 1 "1级故障" 2 "2级故障" 3 "3级故障" ;
VAL_ 2332688223 B2T_TmptSetPoint_31 255 "Invalid" ;
VAL_ 2332688223 TMS_OutWaterTemp_31 255 "无效" ;
VAL_ 2332688223 TMS_BackWaterTemp_31 255 "无效" ;
VAL_ 2332688223 TMS_EnvTemp_31 255 "无效" ;
VAL_ 2332688223 TMS_RequestPower_31 65535 "无效" ;
VAL_ 2332688223 STMS_ThrmStopReason_31 0 "热管理正常停止" 1 "热管理由于其他模块故障停止" 2 "热管理由于热管理模块故障停止" ;
VAL_ 2332688224 B2T_ControlMode_32 0 "关机模式" 1 "制冷模式" 2 "加热模式" 3 "自循环模式" ;
VAL_ 2332688224 TMS_RunState_32 0 "关机模式" 1 "制冷模式" 2 "加热模式" 3 "自循环模式" ;
VAL_ 2332688224 TMS_CommuFault_32 0 "无效" 1 "1级故障" ;
VAL_ 2332688224 TMS_ModeConflict_32 0 "无故障" 1 "故障" ;
VAL_ 2332688224 TMS_MakeBMSStop_32 0 "无故障" 1 "故障" ;
VAL_ 2332688224 TMS_HVRealyState_32 0 "断开状态" 1 "闭合状态" ;
VAL_ 2332688224 TMS_FaultCode_32 0 "无故障" ;
VAL_ 2332688224 TMS_FaultLevel_32 0 "无效" 1 "1级故障" 2 "2级故障" 3 "3级故障" ;
VAL_ 2332688224 B2T_TmptSetPoint_32 255 "Invalid" ;
VAL_ 2332688224 TMS_OutWaterTemp_32 255 "无效" ;
VAL_ 2332688224 TMS_BackWaterTemp_32 255 "无效" ;
VAL_ 2332688224 TMS_EnvTemp_32 255 "无效" ;
VAL_ 2332688224 TMS_RequestPower_32 65535 "无效" ;
VAL_ 2332688224 STMS_ThrmStopReason_32 0 "热管理正常停止" 1 "热管理由于其他模块故障停止" 2 "热管理由于热管理模块故障停止" ;
VAL_ 2332688225 B2T_ControlMode_33 0 "关机模式" 1 "制冷模式" 2 "加热模式" 3 "自循环模式" ;
VAL_ 2332688225 TMS_RunState_33 0 "关机模式" 1 "制冷模式" 2 "加热模式" 3 "自循环模式" ;
VAL_ 2332688225 TMS_CommuFault_33 0 "无效" 1 "1级故障" ;
VAL_ 2332688225 TMS_ModeConflict_33 0 "无故障" 1 "故障" ;
VAL_ 2332688225 TMS_MakeBMSStop_33 0 "无故障" 1 "故障" ;
VAL_ 2332688225 TMS_HVRealyState_33 0 "断开状态" 1 "闭合状态" ;
VAL_ 2332688225 TMS_FaultCode_33 0 "无故障" ;
VAL_ 2332688225 TMS_FaultLevel_33 0 "无效" 1 "1级故障" 2 "2级故障" 3 "3级故障" ;
VAL_ 2332688225 B2T_TmptSetPoint_33 255 "Invalid" ;
VAL_ 2332688225 TMS_OutWaterTemp_33 255 "无效" ;
VAL_ 2332688225 TMS_BackWaterTemp_33 255 "无效" ;
VAL_ 2332688225 TMS_EnvTemp_33 255 "无效" ;
VAL_ 2332688225 TMS_RequestPower_33 65535 "无效" ;
VAL_ 2332688225 STMS_ThrmStopReason_33 0 "热管理正常停止" 1 "热管理由于其他模块故障停止" 2 "热管理由于热管理模块故障停止" ;
VAL_ 2332688226 B2T_ControlMode_34 0 "关机模式" 1 "制冷模式" 2 "加热模式" 3 "自循环模式" ;
VAL_ 2332688226 TMS_RunState_34 0 "关机模式" 1 "制冷模式" 2 "加热模式" 3 "自循环模式" ;
VAL_ 2332688226 TMS_CommuFault_34 0 "无效" 1 "1级故障" ;
VAL_ 2332688226 TMS_ModeConflict_34 0 "无故障" 1 "故障" ;
VAL_ 2332688226 TMS_MakeBMSStop_34 0 "无故障" 1 "故障" ;
VAL_ 2332688226 TMS_HVRealyState_34 0 "断开状态" 1 "闭合状态" ;
VAL_ 2332688226 TMS_FaultCode_34 0 "无故障" ;
VAL_ 2332688226 TMS_FaultLevel_34 0 "无效" 1 "1级故障" 2 "2级故障" 3 "3级故障" ;
VAL_ 2332688226 B2T_TmptSetPoint_34 255 "Invalid" ;
VAL_ 2332688226 TMS_OutWaterTemp_34 255 "无效" ;
VAL_ 2332688226 TMS_BackWaterTemp_34 255 "无效" ;
VAL_ 2332688226 TMS_EnvTemp_34 255 "无效" ;
VAL_ 2332688226 TMS_RequestPower_34 65535 "无效" ;
VAL_ 2332688226 STMS_ThrmStopReason_34 0 "热管理正常停止" 1 "热管理由于其他模块故障停止" 2 "热管理由于热管理模块故障停止" ;
VAL_ 2332688227 B2T_ControlMode_35 0 "关机模式" 1 "制冷模式" 2 "加热模式" 3 "自循环模式" ;
VAL_ 2332688227 TMS_RunState_35 0 "关机模式" 1 "制冷模式" 2 "加热模式" 3 "自循环模式" ;
VAL_ 2332688227 TMS_CommuFault_35 0 "无效" 1 "1级故障" ;
VAL_ 2332688227 TMS_ModeConflict_35 0 "无故障" 1 "故障" ;
VAL_ 2332688227 TMS_MakeBMSStop_35 0 "无故障" 1 "故障" ;
VAL_ 2332688227 TMS_HVRealyState_35 0 "断开状态" 1 "闭合状态" ;
VAL_ 2332688227 TMS_FaultCode_35 0 "无故障" ;
VAL_ 2332688227 TMS_FaultLevel_35 0 "无效" 1 "1级故障" 2 "2级故障" 3 "3级故障" ;
VAL_ 2332688227 B2T_TmptSetPoint_35 255 "Invalid" ;
VAL_ 2332688227 TMS_OutWaterTemp_35 255 "无效" ;
VAL_ 2332688227 TMS_BackWaterTemp_35 255 "无效" ;
VAL_ 2332688227 TMS_EnvTemp_35 255 "无效" ;
VAL_ 2332688227 TMS_RequestPower_35 65535 "无效" ;
VAL_ 2332688227 STMS_ThrmStopReason_35 0 "热管理正常停止" 1 "热管理由于其他模块故障停止" 2 "热管理由于热管理模块故障停止" ;
VAL_ 2332688228 B2T_ControlMode_36 0 "关机模式" 1 "制冷模式" 2 "加热模式" 3 "自循环模式" ;
VAL_ 2332688228 TMS_RunState_36 0 "关机模式" 1 "制冷模式" 2 "加热模式" 3 "自循环模式" ;
VAL_ 2332688228 TMS_CommuFault_36 0 "无效" 1 "1级故障" ;
VAL_ 2332688228 TMS_ModeConflict_36 0 "无故障" 1 "故障" ;
VAL_ 2332688228 TMS_MakeBMSStop_36 0 "无故障" 1 "故障" ;
VAL_ 2332688228 TMS_HVRealyState_36 0 "断开状态" 1 "闭合状态" ;
VAL_ 2332688228 TMS_FaultCode_36 0 "无故障" ;
VAL_ 2332688228 TMS_FaultLevel_36 0 "无效" 1 "1级故障" 2 "2级故障" 3 "3级故障" ;
VAL_ 2332688228 B2T_TmptSetPoint_36 255 "Invalid" ;
VAL_ 2332688228 TMS_OutWaterTemp_36 255 "无效" ;
VAL_ 2332688228 TMS_BackWaterTemp_36 255 "无效" ;
VAL_ 2332688228 TMS_EnvTemp_36 255 "无效" ;
VAL_ 2332688228 TMS_RequestPower_36 65535 "无效" ;
VAL_ 2332688228 STMS_ThrmStopReason_36 0 "热管理正常停止" 1 "热管理由于其他模块故障停止" 2 "热管理由于热管理模块故障停止" ;
VAL_ 2332688229 B2T_ControlMode_37 0 "关机模式" 1 "制冷模式" 2 "加热模式" 3 "自循环模式" ;
VAL_ 2332688229 TMS_RunState_37 0 "关机模式" 1 "制冷模式" 2 "加热模式" 3 "自循环模式" ;
VAL_ 2332688229 TMS_CommuFault_37 0 "无效" 1 "1级故障" ;
VAL_ 2332688229 TMS_ModeConflict_37 0 "无故障" 1 "故障" ;
VAL_ 2332688229 TMS_MakeBMSStop_37 0 "无故障" 1 "故障" ;
VAL_ 2332688229 TMS_HVRealyState_37 0 "断开状态" 1 "闭合状态" ;
VAL_ 2332688229 TMS_FaultCode_37 0 "无故障" ;
VAL_ 2332688229 TMS_FaultLevel_37 0 "无效" 1 "1级故障" 2 "2级故障" 3 "3级故障" ;
VAL_ 2332688229 B2T_TmptSetPoint_37 255 "Invalid" ;
VAL_ 2332688229 TMS_OutWaterTemp_37 255 "无效" ;
VAL_ 2332688229 TMS_BackWaterTemp_37 255 "无效" ;
VAL_ 2332688229 TMS_EnvTemp_37 255 "无效" ;
VAL_ 2332688229 TMS_RequestPower_37 65535 "无效" ;
VAL_ 2332688229 STMS_ThrmStopReason_37 0 "热管理正常停止" 1 "热管理由于其他模块故障停止" 2 "热管理由于热管理模块故障停止" ;
VAL_ 2332688230 B2T_ControlMode_38 0 "关机模式" 1 "制冷模式" 2 "加热模式" 3 "自循环模式" ;
VAL_ 2332688230 TMS_RunState_38 0 "关机模式" 1 "制冷模式" 2 "加热模式" 3 "自循环模式" ;
VAL_ 2332688230 TMS_CommuFault_38 0 "无效" 1 "1级故障" ;
VAL_ 2332688230 TMS_ModeConflict_38 0 "无故障" 1 "故障" ;
VAL_ 2332688230 TMS_MakeBMSStop_38 0 "无故障" 1 "故障" ;
VAL_ 2332688230 TMS_HVRealyState_38 0 "断开状态" 1 "闭合状态" ;
VAL_ 2332688230 TMS_FaultCode_38 0 "无故障" ;
VAL_ 2332688230 TMS_FaultLevel_38 0 "无效" 1 "1级故障" 2 "2级故障" 3 "3级故障" ;
VAL_ 2332688230 B2T_TmptSetPoint_38 255 "Invalid" ;
VAL_ 2332688230 TMS_OutWaterTemp_38 255 "无效" ;
VAL_ 2332688230 TMS_BackWaterTemp_38 255 "无效" ;
VAL_ 2332688230 TMS_EnvTemp_38 255 "无效" ;
VAL_ 2332688230 TMS_RequestPower_38 65535 "无效" ;
VAL_ 2332688230 STMS_ThrmStopReason_38 0 "热管理正常停止" 1 "热管理由于其他模块故障停止" 2 "热管理由于热管理模块故障停止" ;
VAL_ 2332688231 B2T_ControlMode_39 0 "关机模式" 1 "制冷模式" 2 "加热模式" 3 "自循环模式" ;
VAL_ 2332688231 TMS_RunState_39 0 "关机模式" 1 "制冷模式" 2 "加热模式" 3 "自循环模式" ;
VAL_ 2332688231 TMS_CommuFault_39 0 "无效" 1 "1级故障" ;
VAL_ 2332688231 TMS_ModeConflict_39 0 "无故障" 1 "故障" ;
VAL_ 2332688231 TMS_MakeBMSStop_39 0 "无故障" 1 "故障" ;
VAL_ 2332688231 TMS_HVRealyState_39 0 "断开状态" 1 "闭合状态" ;
VAL_ 2332688231 TMS_FaultCode_39 0 "无故障" ;
VAL_ 2332688231 TMS_FaultLevel_39 0 "无效" 1 "1级故障" 2 "2级故障" 3 "3级故障" ;
VAL_ 2332688231 B2T_TmptSetPoint_39 255 "Invalid" ;
VAL_ 2332688231 TMS_OutWaterTemp_39 255 "无效" ;
VAL_ 2332688231 TMS_BackWaterTemp_39 255 "无效" ;
VAL_ 2332688231 TMS_EnvTemp_39 255 "无效" ;
VAL_ 2332688231 TMS_RequestPower_39 65535 "无效" ;
VAL_ 2332688231 STMS_ThrmStopReason_39 0 "热管理正常停止" 1 "热管理由于其他模块故障停止" 2 "热管理由于热管理模块故障停止" ;
VAL_ 2332688232 B2T_ControlMode_40 0 "关机模式" 1 "制冷模式" 2 "加热模式" 3 "自循环模式" ;
VAL_ 2332688232 TMS_RunState_40 0 "关机模式" 1 "制冷模式" 2 "加热模式" 3 "自循环模式" ;
VAL_ 2332688232 TMS_CommuFault_40 0 "无效" 1 "1级故障" ;
VAL_ 2332688232 TMS_ModeConflict_40 0 "无故障" 1 "故障" ;
VAL_ 2332688232 TMS_MakeBMSStop_40 0 "无故障" 1 "故障" ;
VAL_ 2332688232 TMS_HVRealyState_40 0 "断开状态" 1 "闭合状态" ;
VAL_ 2332688232 TMS_FaultCode_40 0 "无故障" ;
VAL_ 2332688232 TMS_FaultLevel_40 0 "无效" 1 "1级故障" 2 "2级故障" 3 "3级故障" ;
VAL_ 2332688232 B2T_TmptSetPoint_40 255 "Invalid" ;
VAL_ 2332688232 TMS_OutWaterTemp_40 255 "无效" ;
VAL_ 2332688232 TMS_BackWaterTemp_40 255 "无效" ;
VAL_ 2332688232 TMS_EnvTemp_40 255 "无效" ;
VAL_ 2332688232 TMS_RequestPower_40 65535 "无效" ;
VAL_ 2332688232 STMS_ThrmStopReason_40 0 "热管理正常停止" 1 "热管理由于其他模块故障停止" 2 "热管理由于热管理模块故障停止" ;
VAL_ 2332688233 B2T_ControlMode_41 0 "关机模式" 1 "制冷模式" 2 "加热模式" 3 "自循环模式" ;
VAL_ 2332688233 TMS_RunState_41 0 "关机模式" 1 "制冷模式" 2 "加热模式" 3 "自循环模式" ;
VAL_ 2332688233 TMS_CommuFault_41 0 "无效" 1 "1级故障" ;
VAL_ 2332688233 TMS_ModeConflict_41 0 "无故障" 1 "故障" ;
VAL_ 2332688233 TMS_MakeBMSStop_41 0 "无故障" 1 "故障" ;
VAL_ 2332688233 TMS_HVRealyState_41 0 "断开状态" 1 "闭合状态" ;
VAL_ 2332688233 TMS_FaultCode_41 0 "无故障" ;
VAL_ 2332688233 TMS_FaultLevel_41 0 "无效" 1 "1级故障" 2 "2级故障" 3 "3级故障" ;
VAL_ 2332688233 B2T_TmptSetPoint_41 255 "Invalid" ;
VAL_ 2332688233 TMS_OutWaterTemp_41 255 "无效" ;
VAL_ 2332688233 TMS_BackWaterTemp_41 255 "无效" ;
VAL_ 2332688233 TMS_EnvTemp_41 255 "无效" ;
VAL_ 2332688233 TMS_RequestPower_41 65535 "无效" ;
VAL_ 2332688233 STMS_ThrmStopReason_41 0 "热管理正常停止" 1 "热管理由于其他模块故障停止" 2 "热管理由于热管理模块故障停止" ;
VAL_ 2332688234 B2T_ControlMode_42 0 "关机模式" 1 "制冷模式" 2 "加热模式" 3 "自循环模式" ;
VAL_ 2332688234 TMS_RunState_42 0 "关机模式" 1 "制冷模式" 2 "加热模式" 3 "自循环模式" ;
VAL_ 2332688234 TMS_CommuFault_42 0 "无效" 1 "1级故障" ;
VAL_ 2332688234 TMS_ModeConflict_42 0 "无故障" 1 "故障" ;
VAL_ 2332688234 TMS_MakeBMSStop_42 0 "无故障" 1 "故障" ;
VAL_ 2332688234 TMS_HVRealyState_42 0 "断开状态" 1 "闭合状态" ;
VAL_ 2332688234 TMS_FaultCode_42 0 "无故障" ;
VAL_ 2332688234 TMS_FaultLevel_42 0 "无效" 1 "1级故障" 2 "2级故障" 3 "3级故障" ;
VAL_ 2332688234 B2T_TmptSetPoint_42 255 "Invalid" ;
VAL_ 2332688234 TMS_OutWaterTemp_42 255 "无效" ;
VAL_ 2332688234 TMS_BackWaterTemp_42 255 "无效" ;
VAL_ 2332688234 TMS_EnvTemp_42 255 "无效" ;
VAL_ 2332688234 TMS_RequestPower_42 65535 "无效" ;
VAL_ 2332688234 STMS_ThrmStopReason_42 0 "热管理正常停止" 1 "热管理由于其他模块故障停止" 2 "热管理由于热管理模块故障停止" ;
VAL_ 2332688235 B2T_ControlMode_43 0 "关机模式" 1 "制冷模式" 2 "加热模式" 3 "自循环模式" ;
VAL_ 2332688235 TMS_RunState_43 0 "关机模式" 1 "制冷模式" 2 "加热模式" 3 "自循环模式" ;
VAL_ 2332688235 TMS_CommuFault_43 0 "无效" 1 "1级故障" ;
VAL_ 2332688235 TMS_ModeConflict_43 0 "无故障" 1 "故障" ;
VAL_ 2332688235 TMS_MakeBMSStop_43 0 "无故障" 1 "故障" ;
VAL_ 2332688235 TMS_HVRealyState_43 0 "断开状态" 1 "闭合状态" ;
VAL_ 2332688235 TMS_FaultCode_43 0 "无故障" ;
VAL_ 2332688235 TMS_FaultLevel_43 0 "无效" 1 "1级故障" 2 "2级故障" 3 "3级故障" ;
VAL_ 2332688235 B2T_TmptSetPoint_43 255 "Invalid" ;
VAL_ 2332688235 TMS_OutWaterTemp_43 255 "无效" ;
VAL_ 2332688235 TMS_BackWaterTemp_43 255 "无效" ;
VAL_ 2332688235 TMS_EnvTemp_43 255 "无效" ;
VAL_ 2332688235 TMS_RequestPower_43 65535 "无效" ;
VAL_ 2332688235 STMS_ThrmStopReason_43 0 "热管理正常停止" 1 "热管理由于其他模块故障停止" 2 "热管理由于热管理模块故障停止" ;
VAL_ 2332688236 B2T_ControlMode_44 0 "关机模式" 1 "制冷模式" 2 "加热模式" 3 "自循环模式" ;
VAL_ 2332688236 TMS_RunState_44 0 "关机模式" 1 "制冷模式" 2 "加热模式" 3 "自循环模式" ;
VAL_ 2332688236 TMS_CommuFault_44 0 "无效" 1 "1级故障" ;
VAL_ 2332688236 TMS_ModeConflict_44 0 "无故障" 1 "故障" ;
VAL_ 2332688236 TMS_MakeBMSStop_44 0 "无故障" 1 "故障" ;
VAL_ 2332688236 TMS_HVRealyState_44 0 "断开状态" 1 "闭合状态" ;
VAL_ 2332688236 TMS_FaultCode_44 0 "无故障" ;
VAL_ 2332688236 TMS_FaultLevel_44 0 "无效" 1 "1级故障" 2 "2级故障" 3 "3级故障" ;
VAL_ 2332688236 B2T_TmptSetPoint_44 255 "Invalid" ;
VAL_ 2332688236 TMS_OutWaterTemp_44 255 "无效" ;
VAL_ 2332688236 TMS_BackWaterTemp_44 255 "无效" ;
VAL_ 2332688236 TMS_EnvTemp_44 255 "无效" ;
VAL_ 2332688236 TMS_RequestPower_44 65535 "无效" ;
VAL_ 2332688236 STMS_ThrmStopReason_44 0 "热管理正常停止" 1 "热管理由于其他模块故障停止" 2 "热管理由于热管理模块故障停止" ;
VAL_ 2332688237 B2T_ControlMode_45 0 "关机模式" 1 "制冷模式" 2 "加热模式" 3 "自循环模式" ;
VAL_ 2332688237 TMS_RunState_45 0 "关机模式" 1 "制冷模式" 2 "加热模式" 3 "自循环模式" ;
VAL_ 2332688237 TMS_CommuFault_45 0 "无效" 1 "1级故障" ;
VAL_ 2332688237 TMS_ModeConflict_45 0 "无故障" 1 "故障" ;
VAL_ 2332688237 TMS_MakeBMSStop_45 0 "无故障" 1 "故障" ;
VAL_ 2332688237 TMS_HVRealyState_45 0 "断开状态" 1 "闭合状态" ;
VAL_ 2332688237 TMS_FaultCode_45 0 "无故障" ;
VAL_ 2332688237 TMS_FaultLevel_45 0 "无效" 1 "1级故障" 2 "2级故障" 3 "3级故障" ;
VAL_ 2332688237 B2T_TmptSetPoint_45 255 "Invalid" ;
VAL_ 2332688237 TMS_OutWaterTemp_45 255 "无效" ;
VAL_ 2332688237 TMS_BackWaterTemp_45 255 "无效" ;
VAL_ 2332688237 TMS_EnvTemp_45 255 "无效" ;
VAL_ 2332688237 TMS_RequestPower_45 65535 "无效" ;
VAL_ 2332688237 STMS_ThrmStopReason_45 0 "热管理正常停止" 1 "热管理由于其他模块故障停止" 2 "热管理由于热管理模块故障停止" ;
VAL_ 2332688238 B2T_ControlMode_46 0 "关机模式" 1 "制冷模式" 2 "加热模式" 3 "自循环模式" ;
VAL_ 2332688238 TMS_RunState_46 0 "关机模式" 1 "制冷模式" 2 "加热模式" 3 "自循环模式" ;
VAL_ 2332688238 TMS_CommuFault_46 0 "无效" 1 "1级故障" ;
VAL_ 2332688238 TMS_ModeConflict_46 0 "无故障" 1 "故障" ;
VAL_ 2332688238 TMS_MakeBMSStop_46 0 "无故障" 1 "故障" ;
VAL_ 2332688238 TMS_HVRealyState_46 0 "断开状态" 1 "闭合状态" ;
VAL_ 2332688238 TMS_FaultCode_46 0 "无故障" ;
VAL_ 2332688238 TMS_FaultLevel_46 0 "无效" 1 "1级故障" 2 "2级故障" 3 "3级故障" ;
VAL_ 2332688238 B2T_TmptSetPoint_46 255 "Invalid" ;
VAL_ 2332688238 TMS_OutWaterTemp_46 255 "无效" ;
VAL_ 2332688238 TMS_BackWaterTemp_46 255 "无效" ;
VAL_ 2332688238 TMS_EnvTemp_46 255 "无效" ;
VAL_ 2332688238 TMS_RequestPower_46 65535 "无效" ;
VAL_ 2332688238 STMS_ThrmStopReason_46 0 "热管理正常停止" 1 "热管理由于其他模块故障停止" 2 "热管理由于热管理模块故障停止" ;
VAL_ 2332688239 B2T_ControlMode_47 0 "关机模式" 1 "制冷模式" 2 "加热模式" 3 "自循环模式" ;
VAL_ 2332688239 TMS_RunState_47 0 "关机模式" 1 "制冷模式" 2 "加热模式" 3 "自循环模式" ;
VAL_ 2332688239 TMS_CommuFault_47 0 "无效" 1 "1级故障" ;
VAL_ 2332688239 TMS_ModeConflict_47 0 "无故障" 1 "故障" ;
VAL_ 2332688239 TMS_MakeBMSStop_47 0 "无故障" 1 "故障" ;
VAL_ 2332688239 TMS_HVRealyState_47 0 "断开状态" 1 "闭合状态" ;
VAL_ 2332688239 TMS_FaultCode_47 0 "无故障" ;
VAL_ 2332688239 TMS_FaultLevel_47 0 "无效" 1 "1级故障" 2 "2级故障" 3 "3级故障" ;
VAL_ 2332688239 B2T_TmptSetPoint_47 255 "Invalid" ;
VAL_ 2332688239 TMS_OutWaterTemp_47 255 "无效" ;
VAL_ 2332688239 TMS_BackWaterTemp_47 255 "无效" ;
VAL_ 2332688239 TMS_EnvTemp_47 255 "无效" ;
VAL_ 2332688239 TMS_RequestPower_47 65535 "无效" ;
VAL_ 2332688239 STMS_ThrmStopReason_47 0 "热管理正常停止" 1 "热管理由于其他模块故障停止" 2 "热管理由于热管理模块故障停止" ;
VAL_ 2332688240 B2T_ControlMode_48 0 "关机模式" 1 "制冷模式" 2 "加热模式" 3 "自循环模式" ;
VAL_ 2332688240 TMS_RunState_48 0 "关机模式" 1 "制冷模式" 2 "加热模式" 3 "自循环模式" ;
VAL_ 2332688240 TMS_CommuFault_48 0 "无效" 1 "1级故障" ;
VAL_ 2332688240 TMS_ModeConflict_48 0 "无故障" 1 "故障" ;
VAL_ 2332688240 TMS_MakeBMSStop_48 0 "无故障" 1 "故障" ;
VAL_ 2332688240 TMS_HVRealyState_48 0 "断开状态" 1 "闭合状态" ;
VAL_ 2332688240 TMS_FaultCode_48 0 "无故障" ;
VAL_ 2332688240 TMS_FaultLevel_48 0 "无效" 1 "1级故障" 2 "2级故障" 3 "3级故障" ;
VAL_ 2332688240 B2T_TmptSetPoint_48 255 "Invalid" ;
VAL_ 2332688240 TMS_OutWaterTemp_48 255 "无效" ;
VAL_ 2332688240 TMS_BackWaterTemp_48 255 "无效" ;
VAL_ 2332688240 TMS_EnvTemp_48 255 "无效" ;
VAL_ 2332688240 TMS_RequestPower_48 65535 "无效" ;
VAL_ 2332688240 STMS_ThrmStopReason_48 0 "热管理正常停止" 1 "热管理由于其他模块故障停止" 2 "热管理由于热管理模块故障停止" ;
VAL_ 2332688241 B2T_ControlMode_49 0 "关机模式" 1 "制冷模式" 2 "加热模式" 3 "自循环模式" ;
VAL_ 2332688241 TMS_RunState_49 0 "关机模式" 1 "制冷模式" 2 "加热模式" 3 "自循环模式" ;
VAL_ 2332688241 TMS_CommuFault_49 0 "无效" 1 "1级故障" ;
VAL_ 2332688241 TMS_ModeConflict_49 0 "无故障" 1 "故障" ;
VAL_ 2332688241 TMS_MakeBMSStop_49 0 "无故障" 1 "故障" ;
VAL_ 2332688241 TMS_HVRealyState_49 0 "断开状态" 1 "闭合状态" ;
VAL_ 2332688241 TMS_FaultCode_49 0 "无故障" ;
VAL_ 2332688241 TMS_FaultLevel_49 0 "无效" 1 "1级故障" 2 "2级故障" 3 "3级故障" ;
VAL_ 2332688241 B2T_TmptSetPoint_49 255 "Invalid" ;
VAL_ 2332688241 TMS_OutWaterTemp_49 255 "无效" ;
VAL_ 2332688241 TMS_BackWaterTemp_49 255 "无效" ;
VAL_ 2332688241 TMS_EnvTemp_49 255 "无效" ;
VAL_ 2332688241 TMS_RequestPower_49 65535 "无效" ;
VAL_ 2332688241 STMS_ThrmStopReason_49 0 "热管理正常停止" 1 "热管理由于其他模块故障停止" 2 "热管理由于热管理模块故障停止" ;
VAL_ 2332688242 B2T_ControlMode_50 0 "关机模式" 1 "制冷模式" 2 "加热模式" 3 "自循环模式" ;
VAL_ 2332688242 TMS_RunState_50 0 "关机模式" 1 "制冷模式" 2 "加热模式" 3 "自循环模式" ;
VAL_ 2332688242 TMS_CommuFault_50 0 "无效" 1 "1级故障" ;
VAL_ 2332688242 TMS_ModeConflict_50 0 "无故障" 1 "故障" ;
VAL_ 2332688242 TMS_MakeBMSStop_50 0 "无故障" 1 "故障" ;
VAL_ 2332688242 TMS_HVRealyState_50 0 "断开状态" 1 "闭合状态" ;
VAL_ 2332688242 TMS_FaultCode_50 0 "无故障" ;
VAL_ 2332688242 TMS_FaultLevel_50 0 "无效" 1 "1级故障" 2 "2级故障" 3 "3级故障" ;
VAL_ 2332688242 B2T_TmptSetPoint_50 255 "Invalid" ;
VAL_ 2332688242 TMS_OutWaterTemp_50 255 "无效" ;
VAL_ 2332688242 TMS_BackWaterTemp_50 255 "无效" ;
VAL_ 2332688242 TMS_EnvTemp_50 255 "无效" ;
VAL_ 2332688242 TMS_RequestPower_50 65535 "无效" ;
VAL_ 2332688242 STMS_ThrmStopReason_50 0 "热管理正常停止" 1 "热管理由于其他模块故障停止" 2 "热管理由于热管理模块故障停止" ;
VAL_ 2332688243 B2T_ControlMode_51 0 "关机模式" 1 "制冷模式" 2 "加热模式" 3 "自循环模式" ;
VAL_ 2332688243 TMS_RunState_51 0 "关机模式" 1 "制冷模式" 2 "加热模式" 3 "自循环模式" ;
VAL_ 2332688243 TMS_CommuFault_51 0 "无效" 1 "1级故障" ;
VAL_ 2332688243 TMS_ModeConflict_51 0 "无故障" 1 "故障" ;
VAL_ 2332688243 TMS_MakeBMSStop_51 0 "无故障" 1 "故障" ;
VAL_ 2332688243 TMS_HVRealyState_51 0 "断开状态" 1 "闭合状态" ;
VAL_ 2332688243 TMS_FaultCode_51 0 "无故障" ;
VAL_ 2332688243 TMS_FaultLevel_51 0 "无效" 1 "1级故障" 2 "2级故障" 3 "3级故障" ;
VAL_ 2332688243 B2T_TmptSetPoint_51 255 "Invalid" ;
VAL_ 2332688243 TMS_OutWaterTemp_51 255 "无效" ;
VAL_ 2332688243 TMS_BackWaterTemp_51 255 "无效" ;
VAL_ 2332688243 TMS_EnvTemp_51 255 "无效" ;
VAL_ 2332688243 TMS_RequestPower_51 65535 "无效" ;
VAL_ 2332688243 STMS_ThrmStopReason_51 0 "热管理正常停止" 1 "热管理由于其他模块故障停止" 2 "热管理由于热管理模块故障停止" ;
VAL_ 2332688244 B2T_ControlMode_52 0 "关机模式" 1 "制冷模式" 2 "加热模式" 3 "自循环模式" ;
VAL_ 2332688244 TMS_RunState_52 0 "关机模式" 1 "制冷模式" 2 "加热模式" 3 "自循环模式" ;
VAL_ 2332688244 TMS_CommuFault_52 0 "无效" 1 "1级故障" ;
VAL_ 2332688244 TMS_ModeConflict_52 0 "无故障" 1 "故障" ;
VAL_ 2332688244 TMS_MakeBMSStop_52 0 "无故障" 1 "故障" ;
VAL_ 2332688244 TMS_HVRealyState_52 0 "断开状态" 1 "闭合状态" ;
VAL_ 2332688244 TMS_FaultCode_52 0 "无故障" ;
VAL_ 2332688244 TMS_FaultLevel_52 0 "无效" 1 "1级故障" 2 "2级故障" 3 "3级故障" ;
VAL_ 2332688244 B2T_TmptSetPoint_52 255 "Invalid" ;
VAL_ 2332688244 TMS_OutWaterTemp_52 255 "无效" ;
VAL_ 2332688244 TMS_BackWaterTemp_52 255 "无效" ;
VAL_ 2332688244 TMS_EnvTemp_52 255 "无效" ;
VAL_ 2332688244 TMS_RequestPower_52 65535 "无效" ;
VAL_ 2332688244 STMS_ThrmStopReason_52 0 "热管理正常停止" 1 "热管理由于其他模块故障停止" 2 "热管理由于热管理模块故障停止" ;
VAL_ 2332688245 B2T_ControlMode_53 0 "关机模式" 1 "制冷模式" 2 "加热模式" 3 "自循环模式" ;
VAL_ 2332688245 TMS_RunState_53 0 "关机模式" 1 "制冷模式" 2 "加热模式" 3 "自循环模式" ;
VAL_ 2332688245 TMS_CommuFault_53 0 "无效" 1 "1级故障" ;
VAL_ 2332688245 TMS_ModeConflict_53 0 "无故障" 1 "故障" ;
VAL_ 2332688245 TMS_MakeBMSStop_53 0 "无故障" 1 "故障" ;
VAL_ 2332688245 TMS_HVRealyState_53 0 "断开状态" 1 "闭合状态" ;
VAL_ 2332688245 TMS_FaultCode_53 0 "无故障" ;
VAL_ 2332688245 TMS_FaultLevel_53 0 "无效" 1 "1级故障" 2 "2级故障" 3 "3级故障" ;
VAL_ 2332688245 B2T_TmptSetPoint_53 255 "Invalid" ;
VAL_ 2332688245 TMS_OutWaterTemp_53 255 "无效" ;
VAL_ 2332688245 TMS_BackWaterTemp_53 255 "无效" ;
VAL_ 2332688245 TMS_EnvTemp_53 255 "无效" ;
VAL_ 2332688245 TMS_RequestPower_53 65535 "无效" ;
VAL_ 2332688245 STMS_ThrmStopReason_53 0 "热管理正常停止" 1 "热管理由于其他模块故障停止" 2 "热管理由于热管理模块故障停止" ;
VAL_ 2332688246 B2T_ControlMode_54 0 "关机模式" 1 "制冷模式" 2 "加热模式" 3 "自循环模式" ;
VAL_ 2332688246 TMS_RunState_54 0 "关机模式" 1 "制冷模式" 2 "加热模式" 3 "自循环模式" ;
VAL_ 2332688246 TMS_CommuFault_54 0 "无效" 1 "1级故障" ;
VAL_ 2332688246 TMS_ModeConflict_54 0 "无故障" 1 "故障" ;
VAL_ 2332688246 TMS_MakeBMSStop_54 0 "无故障" 1 "故障" ;
VAL_ 2332688246 TMS_HVRealyState_54 0 "断开状态" 1 "闭合状态" ;
VAL_ 2332688246 TMS_FaultCode_54 0 "无故障" ;
VAL_ 2332688246 TMS_FaultLevel_54 0 "无效" 1 "1级故障" 2 "2级故障" 3 "3级故障" ;
VAL_ 2332688246 B2T_TmptSetPoint_54 255 "Invalid" ;
VAL_ 2332688246 TMS_OutWaterTemp_54 255 "无效" ;
VAL_ 2332688246 TMS_BackWaterTemp_54 255 "无效" ;
VAL_ 2332688246 TMS_EnvTemp_54 255 "无效" ;
VAL_ 2332688246 TMS_RequestPower_54 65535 "无效" ;
VAL_ 2332688246 STMS_ThrmStopReason_54 0 "热管理正常停止" 1 "热管理由于其他模块故障停止" 2 "热管理由于热管理模块故障停止" ;
VAL_ 2332688247 B2T_ControlMode_55 0 "关机模式" 1 "制冷模式" 2 "加热模式" 3 "自循环模式" ;
VAL_ 2332688247 TMS_RunState_55 0 "关机模式" 1 "制冷模式" 2 "加热模式" 3 "自循环模式" ;
VAL_ 2332688247 TMS_CommuFault_55 0 "无效" 1 "1级故障" ;
VAL_ 2332688247 TMS_ModeConflict_55 0 "无故障" 1 "故障" ;
VAL_ 2332688247 TMS_MakeBMSStop_55 0 "无故障" 1 "故障" ;
VAL_ 2332688247 TMS_HVRealyState_55 0 "断开状态" 1 "闭合状态" ;
VAL_ 2332688247 TMS_FaultCode_55 0 "无故障" ;
VAL_ 2332688247 TMS_FaultLevel_55 0 "无效" 1 "1级故障" 2 "2级故障" 3 "3级故障" ;
VAL_ 2332688247 B2T_TmptSetPoint_55 255 "Invalid" ;
VAL_ 2332688247 TMS_OutWaterTemp_55 255 "无效" ;
VAL_ 2332688247 TMS_BackWaterTemp_55 255 "无效" ;
VAL_ 2332688247 TMS_EnvTemp_55 255 "无效" ;
VAL_ 2332688247 TMS_RequestPower_55 65535 "无效" ;
VAL_ 2332688247 STMS_ThrmStopReason_55 0 "热管理正常停止" 1 "热管理由于其他模块故障停止" 2 "热管理由于热管理模块故障停止" ;
VAL_ 2332688248 B2T_ControlMode_56 0 "关机模式" 1 "制冷模式" 2 "加热模式" 3 "自循环模式" ;
VAL_ 2332688248 TMS_RunState_56 0 "关机模式" 1 "制冷模式" 2 "加热模式" 3 "自循环模式" ;
VAL_ 2332688248 TMS_CommuFault_56 0 "无效" 1 "1级故障" ;
VAL_ 2332688248 TMS_ModeConflict_56 0 "无故障" 1 "故障" ;
VAL_ 2332688248 TMS_MakeBMSStop_56 0 "无故障" 1 "故障" ;
VAL_ 2332688248 TMS_HVRealyState_56 0 "断开状态" 1 "闭合状态" ;
VAL_ 2332688248 TMS_FaultCode_56 0 "无故障" ;
VAL_ 2332688248 TMS_FaultLevel_56 0 "无效" 1 "1级故障" 2 "2级故障" 3 "3级故障" ;
VAL_ 2332688248 B2T_TmptSetPoint_56 255 "Invalid" ;
VAL_ 2332688248 TMS_OutWaterTemp_56 255 "无效" ;
VAL_ 2332688248 TMS_BackWaterTemp_56 255 "无效" ;
VAL_ 2332688248 TMS_EnvTemp_56 255 "无效" ;
VAL_ 2332688248 TMS_RequestPower_56 65535 "无效" ;
VAL_ 2332688248 STMS_ThrmStopReason_56 0 "热管理正常停止" 1 "热管理由于其他模块故障停止" 2 "热管理由于热管理模块故障停止" ;
VAL_ 2332688249 B2T_ControlMode_57 0 "关机模式" 1 "制冷模式" 2 "加热模式" 3 "自循环模式" ;
VAL_ 2332688249 TMS_RunState_57 0 "关机模式" 1 "制冷模式" 2 "加热模式" 3 "自循环模式" ;
VAL_ 2332688249 TMS_CommuFault_57 0 "无效" 1 "1级故障" ;
VAL_ 2332688249 TMS_ModeConflict_57 0 "无故障" 1 "故障" ;
VAL_ 2332688249 TMS_MakeBMSStop_57 0 "无故障" 1 "故障" ;
VAL_ 2332688249 TMS_HVRealyState_57 0 "断开状态" 1 "闭合状态" ;
VAL_ 2332688249 TMS_FaultCode_57 0 "无故障" ;
VAL_ 2332688249 TMS_FaultLevel_57 0 "无效" 1 "1级故障" 2 "2级故障" 3 "3级故障" ;
VAL_ 2332688249 B2T_TmptSetPoint_57 255 "Invalid" ;
VAL_ 2332688249 TMS_OutWaterTemp_57 255 "无效" ;
VAL_ 2332688249 TMS_BackWaterTemp_57 255 "无效" ;
VAL_ 2332688249 TMS_EnvTemp_57 255 "无效" ;
VAL_ 2332688249 TMS_RequestPower_57 65535 "无效" ;
VAL_ 2332688249 STMS_ThrmStopReason_57 0 "热管理正常停止" 1 "热管理由于其他模块故障停止" 2 "热管理由于热管理模块故障停止" ;
VAL_ 2332688250 B2T_ControlMode_58 0 "关机模式" 1 "制冷模式" 2 "加热模式" 3 "自循环模式" ;
VAL_ 2332688250 TMS_RunState_58 0 "关机模式" 1 "制冷模式" 2 "加热模式" 3 "自循环模式" ;
VAL_ 2332688250 TMS_CommuFault_58 0 "无效" 1 "1级故障" ;
VAL_ 2332688250 TMS_ModeConflict_58 0 "无故障" 1 "故障" ;
VAL_ 2332688250 TMS_MakeBMSStop_58 0 "无故障" 1 "故障" ;
VAL_ 2332688250 TMS_HVRealyState_58 0 "断开状态" 1 "闭合状态" ;
VAL_ 2332688250 TMS_FaultCode_58 0 "无故障" ;
VAL_ 2332688250 TMS_FaultLevel_58 0 "无效" 1 "1级故障" 2 "2级故障" 3 "3级故障" ;
VAL_ 2332688250 B2T_TmptSetPoint_58 255 "Invalid" ;
VAL_ 2332688250 TMS_OutWaterTemp_58 255 "无效" ;
VAL_ 2332688250 TMS_BackWaterTemp_58 255 "无效" ;
VAL_ 2332688250 TMS_EnvTemp_58 255 "无效" ;
VAL_ 2332688250 TMS_RequestPower_58 65535 "无效" ;
VAL_ 2332688250 STMS_ThrmStopReason_58 0 "热管理正常停止" 1 "热管理由于其他模块故障停止" 2 "热管理由于热管理模块故障停止" ;
VAL_ 2332688251 B2T_ControlMode_59 0 "关机模式" 1 "制冷模式" 2 "加热模式" 3 "自循环模式" ;
VAL_ 2332688251 TMS_RunState_59 0 "关机模式" 1 "制冷模式" 2 "加热模式" 3 "自循环模式" ;
VAL_ 2332688251 TMS_CommuFault_59 0 "无效" 1 "1级故障" ;
VAL_ 2332688251 TMS_ModeConflict_59 0 "无故障" 1 "故障" ;
VAL_ 2332688251 TMS_MakeBMSStop_59 0 "无故障" 1 "故障" ;
VAL_ 2332688251 TMS_HVRealyState_59 0 "断开状态" 1 "闭合状态" ;
VAL_ 2332688251 TMS_FaultCode_59 0 "无故障" ;
VAL_ 2332688251 TMS_FaultLevel_59 0 "无效" 1 "1级故障" 2 "2级故障" 3 "3级故障" ;
VAL_ 2332688251 B2T_TmptSetPoint_59 255 "Invalid" ;
VAL_ 2332688251 TMS_OutWaterTemp_59 255 "无效" ;
VAL_ 2332688251 TMS_BackWaterTemp_59 255 "无效" ;
VAL_ 2332688251 TMS_EnvTemp_59 255 "无效" ;
VAL_ 2332688251 TMS_RequestPower_59 65535 "无效" ;
VAL_ 2332688251 STMS_ThrmStopReason_59 0 "热管理正常停止" 1 "热管理由于其他模块故障停止" 2 "热管理由于热管理模块故障停止" ;
VAL_ 2332688252 B2T_ControlMode_60 0 "关机模式" 1 "制冷模式" 2 "加热模式" 3 "自循环模式" ;
VAL_ 2332688252 TMS_RunState_60 0 "关机模式" 1 "制冷模式" 2 "加热模式" 3 "自循环模式" ;
VAL_ 2332688252 TMS_CommuFault_60 0 "无效" 1 "1级故障" ;
VAL_ 2332688252 TMS_ModeConflict_60 0 "无故障" 1 "故障" ;
VAL_ 2332688252 TMS_MakeBMSStop_60 0 "无故障" 1 "故障" ;
VAL_ 2332688252 TMS_HVRealyState_60 0 "断开状态" 1 "闭合状态" ;
VAL_ 2332688252 TMS_FaultCode_60 0 "无故障" ;
VAL_ 2332688252 TMS_FaultLevel_60 0 "无效" 1 "1级故障" 2 "2级故障" 3 "3级故障" ;
VAL_ 2332688252 B2T_TmptSetPoint_60 255 "Invalid" ;
VAL_ 2332688252 TMS_OutWaterTemp_60 255 "无效" ;
VAL_ 2332688252 TMS_BackWaterTemp_60 255 "无效" ;
VAL_ 2332688252 TMS_EnvTemp_60 255 "无效" ;
VAL_ 2332688252 TMS_RequestPower_60 65535 "无效" ;
VAL_ 2332688252 STMS_ThrmStopReason_60 0 "热管理正常停止" 1 "热管理由于其他模块故障停止" 2 "热管理由于热管理模块故障停止" ;
VAL_ 2332688253 B2T_ControlMode_61 0 "关机模式" 1 "制冷模式" 2 "加热模式" 3 "自循环模式" ;
VAL_ 2332688253 TMS_RunState_61 0 "关机模式" 1 "制冷模式" 2 "加热模式" 3 "自循环模式" ;
VAL_ 2332688253 TMS_CommuFault_61 0 "无效" 1 "1级故障" ;
VAL_ 2332688253 TMS_ModeConflict_61 0 "无故障" 1 "故障" ;
VAL_ 2332688253 TMS_MakeBMSStop_61 0 "无故障" 1 "故障" ;
VAL_ 2332688253 TMS_HVRealyState_61 0 "断开状态" 1 "闭合状态" ;
VAL_ 2332688253 TMS_FaultCode_61 0 "无故障" ;
VAL_ 2332688253 TMS_FaultLevel_61 0 "无效" 1 "1级故障" 2 "2级故障" 3 "3级故障" ;
VAL_ 2332688253 B2T_TmptSetPoint_61 255 "Invalid" ;
VAL_ 2332688253 TMS_OutWaterTemp_61 255 "无效" ;
VAL_ 2332688253 TMS_BackWaterTemp_61 255 "无效" ;
VAL_ 2332688253 TMS_EnvTemp_61 255 "无效" ;
VAL_ 2332688253 TMS_RequestPower_61 65535 "无效" ;
VAL_ 2332688253 STMS_ThrmStopReason_61 0 "热管理正常停止" 1 "热管理由于其他模块故障停止" 2 "热管理由于热管理模块故障停止" ;
VAL_ 2332688254 B2T_ControlMode_62 0 "关机模式" 1 "制冷模式" 2 "加热模式" 3 "自循环模式" ;
VAL_ 2332688254 TMS_RunState_62 0 "关机模式" 1 "制冷模式" 2 "加热模式" 3 "自循环模式" ;
VAL_ 2332688254 TMS_CommuFault_62 0 "无效" 1 "1级故障" ;
VAL_ 2332688254 TMS_ModeConflict_62 0 "无故障" 1 "故障" ;
VAL_ 2332688254 TMS_MakeBMSStop_62 0 "无故障" 1 "故障" ;
VAL_ 2332688254 TMS_HVRealyState_62 0 "断开状态" 1 "闭合状态" ;
VAL_ 2332688254 TMS_FaultCode_62 0 "无故障" ;
VAL_ 2332688254 TMS_FaultLevel_62 0 "无效" 1 "1级故障" 2 "2级故障" 3 "3级故障" ;
VAL_ 2332688254 B2T_TmptSetPoint_62 255 "Invalid" ;
VAL_ 2332688254 TMS_OutWaterTemp_62 255 "无效" ;
VAL_ 2332688254 TMS_BackWaterTemp_62 255 "无效" ;
VAL_ 2332688254 TMS_EnvTemp_62 255 "无效" ;
VAL_ 2332688254 TMS_RequestPower_62 65535 "无效" ;
VAL_ 2332688254 STMS_ThrmStopReason_62 0 "热管理正常停止" 1 "热管理由于其他模块故障停止" 2 "热管理由于热管理模块故障停止" ;
VAL_ 2332688255 B2T_ControlMode_63 0 "关机模式" 1 "制冷模式" 2 "加热模式" 3 "自循环模式" ;
VAL_ 2332688255 TMS_RunState_63 0 "关机模式" 1 "制冷模式" 2 "加热模式" 3 "自循环模式" ;
VAL_ 2332688255 TMS_CommuFault_63 0 "无效" 1 "1级故障" ;
VAL_ 2332688255 TMS_ModeConflict_63 0 "无故障" 1 "故障" ;
VAL_ 2332688255 TMS_MakeBMSStop_63 0 "无故障" 1 "故障" ;
VAL_ 2332688255 TMS_HVRealyState_63 0 "断开状态" 1 "闭合状态" ;
VAL_ 2332688255 TMS_FaultCode_63 0 "无故障" ;
VAL_ 2332688255 TMS_FaultLevel_63 0 "无效" 1 "1级故障" 2 "2级故障" 3 "3级故障" ;
VAL_ 2332688255 B2T_TmptSetPoint_63 255 "Invalid" ;
VAL_ 2332688255 TMS_OutWaterTemp_63 255 "无效" ;
VAL_ 2332688255 TMS_BackWaterTemp_63 255 "无效" ;
VAL_ 2332688255 TMS_EnvTemp_63 255 "无效" ;
VAL_ 2332688255 TMS_RequestPower_63 65535 "无效" ;
VAL_ 2332688255 STMS_ThrmStopReason_63 0 "热管理正常停止" 1 "热管理由于其他模块故障停止" 2 "热管理由于热管理模块故障停止" ;
VAL_ 2332753729 FireFault_Level1_01 0 "无故障" 1 "故障" ;
VAL_ 2332753729 FireFault_Level2_01 0 "无故障" 1 "故障" ;
VAL_ 2332753729 TempState_01 0 "无报警" 1 "温感报警" ;
VAL_ 2332753729 FogState_01 0 "无报警" 1 "烟感告警" ;
VAL_ 2332753729 AerosolState_01 0 "未触发" 1 "已触发" ;
VAL_ 2332753729 AerosolFaultState_01 0 "无故障" 1 "异常开启" 2 "异常关闭" ;
VAL_ 2332753729 DoorState_01 0 "柜门闭合" 1 "柜门开启" ;
VAL_ 2332753729 ControlBoxFanState_01 0 "未开启" 1 "已开启" ;
VAL_ 2332753729 ControlBoxTempHighWarning_01 0 "无报警" 1 "主控箱高温报警" ;
VAL_ 2332753729 PowerSWState_01 0 "未触发" 1 "已触发" ;
VAL_ 2332753729 FaultClearCommand_01 0 "不清除" 1 "清除全部极限故障" ;
VAL_ 2332753730 FireFault_Level1_02 0 "无故障" 1 "故障" ;
VAL_ 2332753730 FireFault_Level2_02 0 "无故障" 1 "故障" ;
VAL_ 2332753730 TempState_02 0 "无报警" 1 "温感报警" ;
VAL_ 2332753730 FogState_02 0 "无报警" 1 "烟感告警" ;
VAL_ 2332753730 AerosolState_02 0 "未触发" 1 "已触发" ;
VAL_ 2332753730 AerosolFaultState_02 0 "无故障" 1 "异常开启" 2 "异常关闭" ;
VAL_ 2332753730 DoorState_02 0 "柜门闭合" 1 "柜门开启" ;
VAL_ 2332753730 ControlBoxFanState_02 0 "未开启" 1 "已开启" ;
VAL_ 2332753730 ControlBoxTempHighWarning_02 0 "无报警" 1 "主控箱高温报警" ;
VAL_ 2332753730 PowerSWState_02 0 "未触发" 1 "已触发" ;
VAL_ 2332753730 FaultClearCommand_02 0 "不清除" 1 "清除全部极限故障" ;
VAL_ 2332753731 FireFault_Level1_03 0 "无故障" 1 "故障" ;
VAL_ 2332753731 FireFault_Level2_03 0 "无故障" 1 "故障" ;
VAL_ 2332753731 TempState_03 0 "无报警" 1 "温感报警" ;
VAL_ 2332753731 FogState_03 0 "无报警" 1 "烟感告警" ;
VAL_ 2332753731 AerosolState_03 0 "未触发" 1 "已触发" ;
VAL_ 2332753731 AerosolFaultState_03 0 "无故障" 1 "异常开启" 2 "异常关闭" ;
VAL_ 2332753731 DoorState_03 0 "柜门闭合" 1 "柜门开启" ;
VAL_ 2332753731 ControlBoxFanState_03 0 "未开启" 1 "已开启" ;
VAL_ 2332753731 ControlBoxTempHighWarning_03 0 "无报警" 1 "主控箱高温报警" ;
VAL_ 2332753731 PowerSWState_03 0 "未触发" 1 "已触发" ;
VAL_ 2332753731 FaultClearCommand_03 0 "不清除" 1 "清除全部极限故障" ;
VAL_ 2332753732 FireFault_Level1_04 0 "无故障" 1 "故障" ;
VAL_ 2332753732 FireFault_Level2_04 0 "无故障" 1 "故障" ;
VAL_ 2332753732 TempState_04 0 "无报警" 1 "温感报警" ;
VAL_ 2332753732 FogState_04 0 "无报警" 1 "烟感告警" ;
VAL_ 2332753732 AerosolState_04 0 "未触发" 1 "已触发" ;
VAL_ 2332753732 AerosolFaultState_04 0 "无故障" 1 "异常开启" 2 "异常关闭" ;
VAL_ 2332753732 DoorState_04 0 "柜门闭合" 1 "柜门开启" ;
VAL_ 2332753732 ControlBoxFanState_04 0 "未开启" 1 "已开启" ;
VAL_ 2332753732 ControlBoxTempHighWarning_04 0 "无报警" 1 "主控箱高温报警" ;
VAL_ 2332753732 PowerSWState_04 0 "未触发" 1 "已触发" ;
VAL_ 2332753732 FaultClearCommand_04 0 "不清除" 1 "清除全部极限故障" ;
VAL_ 2332753733 FireFault_Level1_05 0 "无故障" 1 "故障" ;
VAL_ 2332753733 FireFault_Level2_05 0 "无故障" 1 "故障" ;
VAL_ 2332753733 TempState_05 0 "无报警" 1 "温感报警" ;
VAL_ 2332753733 FogState_05 0 "无报警" 1 "烟感告警" ;
VAL_ 2332753733 AerosolState_05 0 "未触发" 1 "已触发" ;
VAL_ 2332753733 AerosolFaultState_05 0 "无故障" 1 "异常开启" 2 "异常关闭" ;
VAL_ 2332753733 DoorState_05 0 "柜门闭合" 1 "柜门开启" ;
VAL_ 2332753733 ControlBoxFanState_05 0 "未开启" 1 "已开启" ;
VAL_ 2332753733 ControlBoxTempHighWarning_05 0 "无报警" 1 "主控箱高温报警" ;
VAL_ 2332753733 PowerSWState_05 0 "未触发" 1 "已触发" ;
VAL_ 2332753733 FaultClearCommand_05 0 "不清除" 1 "清除全部极限故障" ;
VAL_ 2332753734 FireFault_Level1_06 0 "无故障" 1 "故障" ;
VAL_ 2332753734 FireFault_Level2_06 0 "无故障" 1 "故障" ;
VAL_ 2332753734 TempState_06 0 "无报警" 1 "温感报警" ;
VAL_ 2332753734 FogState_06 0 "无报警" 1 "烟感告警" ;
VAL_ 2332753734 AerosolState_06 0 "未触发" 1 "已触发" ;
VAL_ 2332753734 AerosolFaultState_06 0 "无故障" 1 "异常开启" 2 "异常关闭" ;
VAL_ 2332753734 DoorState_06 0 "柜门闭合" 1 "柜门开启" ;
VAL_ 2332753734 ControlBoxFanState_06 0 "未开启" 1 "已开启" ;
VAL_ 2332753734 ControlBoxTempHighWarning_06 0 "无报警" 1 "主控箱高温报警" ;
VAL_ 2332753734 PowerSWState_06 0 "未触发" 1 "已触发" ;
VAL_ 2332753734 FaultClearCommand_06 0 "不清除" 1 "清除全部极限故障" ;
VAL_ 2332753735 FireFault_Level1_07 0 "无故障" 1 "故障" ;
VAL_ 2332753735 FireFault_Level2_07 0 "无故障" 1 "故障" ;
VAL_ 2332753735 TempState_07 0 "无报警" 1 "温感报警" ;
VAL_ 2332753735 FogState_07 0 "无报警" 1 "烟感告警" ;
VAL_ 2332753735 AerosolState_07 0 "未触发" 1 "已触发" ;
VAL_ 2332753735 AerosolFaultState_07 0 "无故障" 1 "异常开启" 2 "异常关闭" ;
VAL_ 2332753735 DoorState_07 0 "柜门闭合" 1 "柜门开启" ;
VAL_ 2332753735 ControlBoxFanState_07 0 "未开启" 1 "已开启" ;
VAL_ 2332753735 ControlBoxTempHighWarning_07 0 "无报警" 1 "主控箱高温报警" ;
VAL_ 2332753735 PowerSWState_07 0 "未触发" 1 "已触发" ;
VAL_ 2332753735 FaultClearCommand_07 0 "不清除" 1 "清除全部极限故障" ;
VAL_ 2332753736 FireFault_Level1_08 0 "无故障" 1 "故障" ;
VAL_ 2332753736 FireFault_Level2_08 0 "无故障" 1 "故障" ;
VAL_ 2332753736 TempState_08 0 "无报警" 1 "温感报警" ;
VAL_ 2332753736 FogState_08 0 "无报警" 1 "烟感告警" ;
VAL_ 2332753736 AerosolState_08 0 "未触发" 1 "已触发" ;
VAL_ 2332753736 AerosolFaultState_08 0 "无故障" 1 "异常开启" 2 "异常关闭" ;
VAL_ 2332753736 DoorState_08 0 "柜门闭合" 1 "柜门开启" ;
VAL_ 2332753736 ControlBoxFanState_08 0 "未开启" 1 "已开启" ;
VAL_ 2332753736 ControlBoxTempHighWarning_08 0 "无报警" 1 "主控箱高温报警" ;
VAL_ 2332753736 PowerSWState_08 0 "未触发" 1 "已触发" ;
VAL_ 2332753736 FaultClearCommand_08 0 "不清除" 1 "清除全部极限故障" ;
VAL_ 2332753737 FireFault_Level1_09 0 "无故障" 1 "故障" ;
VAL_ 2332753737 FireFault_Level2_09 0 "无故障" 1 "故障" ;
VAL_ 2332753737 TempState_09 0 "无报警" 1 "温感报警" ;
VAL_ 2332753737 FogState_09 0 "无报警" 1 "烟感告警" ;
VAL_ 2332753737 AerosolState_09 0 "未触发" 1 "已触发" ;
VAL_ 2332753737 AerosolFaultState_09 0 "无故障" 1 "异常开启" 2 "异常关闭" ;
VAL_ 2332753737 DoorState_09 0 "柜门闭合" 1 "柜门开启" ;
VAL_ 2332753737 ControlBoxFanState_09 0 "未开启" 1 "已开启" ;
VAL_ 2332753737 ControlBoxTempHighWarning_09 0 "无报警" 1 "主控箱高温报警" ;
VAL_ 2332753737 PowerSWState_09 0 "未触发" 1 "已触发" ;
VAL_ 2332753737 FaultClearCommand_09 0 "不清除" 1 "清除全部极限故障" ;
VAL_ 2332753738 FireFault_Level1_10 0 "无故障" 1 "故障" ;
VAL_ 2332753738 FireFault_Level2_10 0 "无故障" 1 "故障" ;
VAL_ 2332753738 TempState_10 0 "无报警" 1 "温感报警" ;
VAL_ 2332753738 FogState_10 0 "无报警" 1 "烟感告警" ;
VAL_ 2332753738 AerosolState_10 0 "未触发" 1 "已触发" ;
VAL_ 2332753738 AerosolFaultState_10 0 "无故障" 1 "异常开启" 2 "异常关闭" ;
VAL_ 2332753738 DoorState_10 0 "柜门闭合" 1 "柜门开启" ;
VAL_ 2332753738 ControlBoxFanState_10 0 "未开启" 1 "已开启" ;
VAL_ 2332753738 ControlBoxTempHighWarning_10 0 "无报警" 1 "主控箱高温报警" ;
VAL_ 2332753738 PowerSWState_10 0 "未触发" 1 "已触发" ;
VAL_ 2332753738 FaultClearCommand_10 0 "不清除" 1 "清除全部极限故障" ;
VAL_ 2332753739 FireFault_Level1_11 0 "无故障" 1 "故障" ;
VAL_ 2332753739 FireFault_Level2_11 0 "无故障" 1 "故障" ;
VAL_ 2332753739 TempState_11 0 "无报警" 1 "温感报警" ;
VAL_ 2332753739 FogState_11 0 "无报警" 1 "烟感告警" ;
VAL_ 2332753739 AerosolState_11 0 "未触发" 1 "已触发" ;
VAL_ 2332753739 AerosolFaultState_11 0 "无故障" 1 "异常开启" 2 "异常关闭" ;
VAL_ 2332753739 DoorState_11 0 "柜门闭合" 1 "柜门开启" ;
VAL_ 2332753739 ControlBoxFanState_11 0 "未开启" 1 "已开启" ;
VAL_ 2332753739 ControlBoxTempHighWarning_11 0 "无报警" 1 "主控箱高温报警" ;
VAL_ 2332753739 PowerSWState_11 0 "未触发" 1 "已触发" ;
VAL_ 2332753739 FaultClearCommand_11 0 "不清除" 1 "清除全部极限故障" ;
VAL_ 2332753740 FireFault_Level1_12 0 "无故障" 1 "故障" ;
VAL_ 2332753740 FireFault_Level2_12 0 "无故障" 1 "故障" ;
VAL_ 2332753740 TempState_12 0 "无报警" 1 "温感报警" ;
VAL_ 2332753740 FogState_12 0 "无报警" 1 "烟感告警" ;
VAL_ 2332753740 AerosolState_12 0 "未触发" 1 "已触发" ;
VAL_ 2332753740 AerosolFaultState_12 0 "无故障" 1 "异常开启" 2 "异常关闭" ;
VAL_ 2332753740 DoorState_12 0 "柜门闭合" 1 "柜门开启" ;
VAL_ 2332753740 ControlBoxFanState_12 0 "未开启" 1 "已开启" ;
VAL_ 2332753740 ControlBoxTempHighWarning_12 0 "无报警" 1 "主控箱高温报警" ;
VAL_ 2332753740 PowerSWState_12 0 "未触发" 1 "已触发" ;
VAL_ 2332753740 FaultClearCommand_12 0 "不清除" 1 "清除全部极限故障" ;
VAL_ 2332753741 FireFault_Level1_13 0 "无故障" 1 "故障" ;
VAL_ 2332753741 FireFault_Level2_13 0 "无故障" 1 "故障" ;
VAL_ 2332753741 TempState_13 0 "无报警" 1 "温感报警" ;
VAL_ 2332753741 FogState_13 0 "无报警" 1 "烟感告警" ;
VAL_ 2332753741 AerosolState_13 0 "未触发" 1 "已触发" ;
VAL_ 2332753741 AerosolFaultState_13 0 "无故障" 1 "异常开启" 2 "异常关闭" ;
VAL_ 2332753741 DoorState_13 0 "柜门闭合" 1 "柜门开启" ;
VAL_ 2332753741 ControlBoxFanState_13 0 "未开启" 1 "已开启" ;
VAL_ 2332753741 ControlBoxTempHighWarning_13 0 "无报警" 1 "主控箱高温报警" ;
VAL_ 2332753741 PowerSWState_13 0 "未触发" 1 "已触发" ;
VAL_ 2332753741 FaultClearCommand_13 0 "不清除" 1 "清除全部极限故障" ;
VAL_ 2332753742 FireFault_Level1_14 0 "无故障" 1 "故障" ;
VAL_ 2332753742 FireFault_Level2_14 0 "无故障" 1 "故障" ;
VAL_ 2332753742 TempState_14 0 "无报警" 1 "温感报警" ;
VAL_ 2332753742 FogState_14 0 "无报警" 1 "烟感告警" ;
VAL_ 2332753742 AerosolState_14 0 "未触发" 1 "已触发" ;
VAL_ 2332753742 AerosolFaultState_14 0 "无故障" 1 "异常开启" 2 "异常关闭" ;
VAL_ 2332753742 DoorState_14 0 "柜门闭合" 1 "柜门开启" ;
VAL_ 2332753742 ControlBoxFanState_14 0 "未开启" 1 "已开启" ;
VAL_ 2332753742 ControlBoxTempHighWarning_14 0 "无报警" 1 "主控箱高温报警" ;
VAL_ 2332753742 PowerSWState_14 0 "未触发" 1 "已触发" ;
VAL_ 2332753742 FaultClearCommand_14 0 "不清除" 1 "清除全部极限故障" ;
VAL_ 2332753743 FireFault_Level1_15 0 "无故障" 1 "故障" ;
VAL_ 2332753743 FireFault_Level2_15 0 "无故障" 1 "故障" ;
VAL_ 2332753743 TempState_15 0 "无报警" 1 "温感报警" ;
VAL_ 2332753743 FogState_15 0 "无报警" 1 "烟感告警" ;
VAL_ 2332753743 AerosolState_15 0 "未触发" 1 "已触发" ;
VAL_ 2332753743 AerosolFaultState_15 0 "无故障" 1 "异常开启" 2 "异常关闭" ;
VAL_ 2332753743 DoorState_15 0 "柜门闭合" 1 "柜门开启" ;
VAL_ 2332753743 ControlBoxFanState_15 0 "未开启" 1 "已开启" ;
VAL_ 2332753743 ControlBoxTempHighWarning_15 0 "无报警" 1 "主控箱高温报警" ;
VAL_ 2332753743 PowerSWState_15 0 "未触发" 1 "已触发" ;
VAL_ 2332753743 FaultClearCommand_15 0 "不清除" 1 "清除全部极限故障" ;
VAL_ 2332753744 FireFault_Level1_16 0 "无故障" 1 "故障" ;
VAL_ 2332753744 FireFault_Level2_16 0 "无故障" 1 "故障" ;
VAL_ 2332753744 TempState_16 0 "无报警" 1 "温感报警" ;
VAL_ 2332753744 FogState_16 0 "无报警" 1 "烟感告警" ;
VAL_ 2332753744 AerosolState_16 0 "未触发" 1 "已触发" ;
VAL_ 2332753744 AerosolFaultState_16 0 "无故障" 1 "异常开启" 2 "异常关闭" ;
VAL_ 2332753744 DoorState_16 0 "柜门闭合" 1 "柜门开启" ;
VAL_ 2332753744 ControlBoxFanState_16 0 "未开启" 1 "已开启" ;
VAL_ 2332753744 ControlBoxTempHighWarning_16 0 "无报警" 1 "主控箱高温报警" ;
VAL_ 2332753744 PowerSWState_16 0 "未触发" 1 "已触发" ;
VAL_ 2332753744 FaultClearCommand_16 0 "不清除" 1 "清除全部极限故障" ;
VAL_ 2332753745 FireFault_Level1_17 0 "无故障" 1 "故障" ;
VAL_ 2332753745 FireFault_Level2_17 0 "无故障" 1 "故障" ;
VAL_ 2332753745 TempState_17 0 "无报警" 1 "温感报警" ;
VAL_ 2332753745 FogState_17 0 "无报警" 1 "烟感告警" ;
VAL_ 2332753745 AerosolState_17 0 "未触发" 1 "已触发" ;
VAL_ 2332753745 AerosolFaultState_17 0 "无故障" 1 "异常开启" 2 "异常关闭" ;
VAL_ 2332753745 DoorState_17 0 "柜门闭合" 1 "柜门开启" ;
VAL_ 2332753745 ControlBoxFanState_17 0 "未开启" 1 "已开启" ;
VAL_ 2332753745 ControlBoxTempHighWarning_17 0 "无报警" 1 "主控箱高温报警" ;
VAL_ 2332753745 PowerSWState_17 0 "未触发" 1 "已触发" ;
VAL_ 2332753745 FaultClearCommand_17 0 "不清除" 1 "清除全部极限故障" ;
VAL_ 2332753746 FireFault_Level1_18 0 "无故障" 1 "故障" ;
VAL_ 2332753746 FireFault_Level2_18 0 "无故障" 1 "故障" ;
VAL_ 2332753746 TempState_18 0 "无报警" 1 "温感报警" ;
VAL_ 2332753746 FogState_18 0 "无报警" 1 "烟感告警" ;
VAL_ 2332753746 AerosolState_18 0 "未触发" 1 "已触发" ;
VAL_ 2332753746 AerosolFaultState_18 0 "无故障" 1 "异常开启" 2 "异常关闭" ;
VAL_ 2332753746 DoorState_18 0 "柜门闭合" 1 "柜门开启" ;
VAL_ 2332753746 ControlBoxFanState_18 0 "未开启" 1 "已开启" ;
VAL_ 2332753746 ControlBoxTempHighWarning_18 0 "无报警" 1 "主控箱高温报警" ;
VAL_ 2332753746 PowerSWState_18 0 "未触发" 1 "已触发" ;
VAL_ 2332753746 FaultClearCommand_18 0 "不清除" 1 "清除全部极限故障" ;
VAL_ 2332753747 FireFault_Level1_19 0 "无故障" 1 "故障" ;
VAL_ 2332753747 FireFault_Level2_19 0 "无故障" 1 "故障" ;
VAL_ 2332753747 TempState_19 0 "无报警" 1 "温感报警" ;
VAL_ 2332753747 FogState_19 0 "无报警" 1 "烟感告警" ;
VAL_ 2332753747 AerosolState_19 0 "未触发" 1 "已触发" ;
VAL_ 2332753747 AerosolFaultState_19 0 "无故障" 1 "异常开启" 2 "异常关闭" ;
VAL_ 2332753747 DoorState_19 0 "柜门闭合" 1 "柜门开启" ;
VAL_ 2332753747 ControlBoxFanState_19 0 "未开启" 1 "已开启" ;
VAL_ 2332753747 ControlBoxTempHighWarning_19 0 "无报警" 1 "主控箱高温报警" ;
VAL_ 2332753747 PowerSWState_19 0 "未触发" 1 "已触发" ;
VAL_ 2332753747 FaultClearCommand_19 0 "不清除" 1 "清除全部极限故障" ;
VERSION ""

NS_ :

BS_:

BU_: MBMU PC SBMU IMM ETH DCDC LEMS

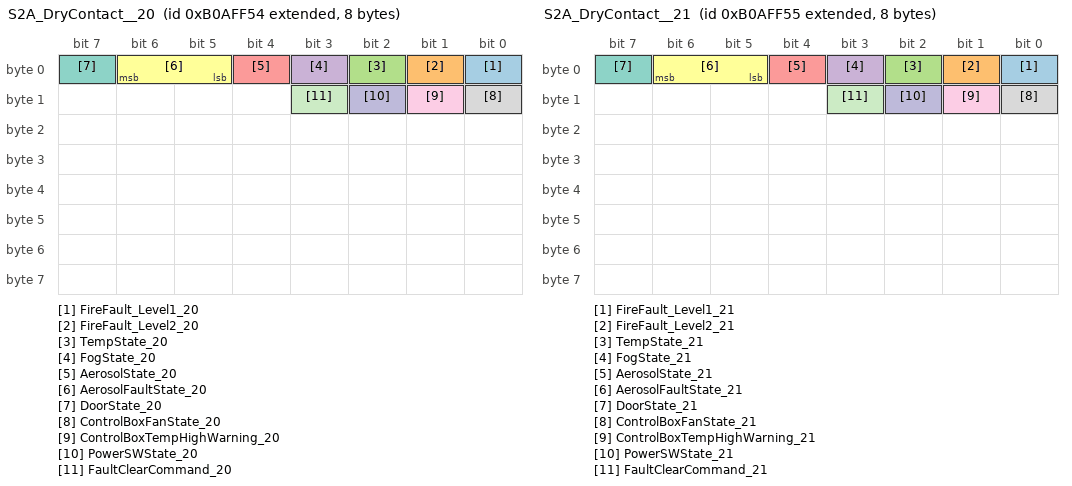
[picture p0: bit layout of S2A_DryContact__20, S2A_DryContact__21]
BO_ 2332753748 S2A_DryContact__20: 8 SBMU
 SG_ FireFault_Level1_20 : 0|1@1+ (1,0) [0|1] ""  MBMU,PC
 SG_ FireFault_Level2_20 : 1|1@1+ (1,0) [0|1] ""  MBMU,PC
 SG_ TempState_20 : 2|1@1+ (1,0) [0|1] ""  MBMU,PC
 SG_ FogState_20 : 3|1@1+ (1,0) [0|1] ""  MBMU,PC
 SG_ AerosolState_20 : 4|1@1+ (1,0) [0|1] ""  MBMU,PC
 SG_ AerosolFaultState_20 : 5|2@1+ (1,0) [0|3] ""  MBMU,PC
 SG_ DoorState_20 : 7|1@1+ (1,0) [0|1] ""  MBMU,PC
 SG_ ControlBoxFanState_20 : 8|1@1+ (1,0) [0|1] ""  MBMU,PC
 SG_ ControlBoxTempHighWarning_20 : 9|1@1+ (1,0) [0|1] ""  MBMU,PC
 SG_ PowerSWState_20 : 10|1@1+ (1,0) [0|1] ""  MBMU,PC
 SG_ FaultClearCommand_20 : 11|1@1+ (1,0) [0|1] ""  MBMU,PC

BO_ 2332753749 S2A_DryContact__21: 8 SBMU
 SG_ FireFault_Level1_21 : 0|1@1+ (1,0) [0|1] ""  MBMU,PC
 SG_ FireFault_Level2_21 : 1|1@1+ (1,0) [0|1] ""  MBMU,PC
 SG_ TempState_21 : 2|1@1+ (1,0) [0|1] ""  MBMU,PC
 SG_ FogState_21 : 3|1@1+ (1,0) [0|1] ""  MBMU,PC
 SG_ AerosolState_21 : 4|1@1+ (1,0) [0|1] ""  MBMU,PC
 SG_ AerosolFaultState_21 : 5|2@1+ (1,0) [0|3] ""  MBMU,PC
 SG_ DoorState_21 : 7|1@1+ (1,0) [0|1] ""  MBMU,PC
 SG_ ControlBoxFanState_21 : 8|1@1+ (1,0) [0|1] ""  MBMU,PC
 SG_ ControlBoxTempHighWarning_21 : 9|1@1+ (1,0) [0|1] ""  MBMU,PC
 SG_ PowerSWState_21 : 10|1@1+ (1,0) [0|1] ""  MBMU,PC
 SG_ FaultClearCommand_21 : 11|1@1+ (1,0) [0|1] ""  MBMU,PC

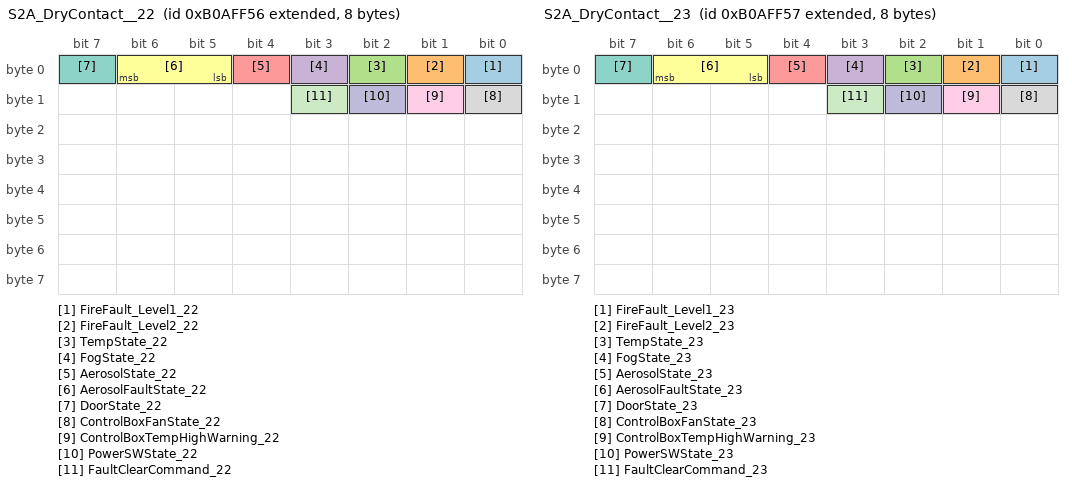
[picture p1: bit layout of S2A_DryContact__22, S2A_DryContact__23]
BO_ 2332753750 S2A_DryContact__22: 8 SBMU
 SG_ FireFault_Level1_22 : 0|1@1+ (1,0) [0|1] ""  MBMU,PC
 SG_ FireFault_Level2_22 : 1|1@1+ (1,0) [0|1] ""  MBMU,PC
 SG_ TempState_22 : 2|1@1+ (1,0) [0|1] ""  MBMU,PC
 SG_ FogState_22 : 3|1@1+ (1,0) [0|1] ""  MBMU,PC
 SG_ AerosolState_22 : 4|1@1+ (1,0) [0|1] ""  MBMU,PC
 SG_ AerosolFaultState_22 : 5|2@1+ (1,0) [0|3] ""  MBMU,PC
 SG_ DoorState_22 : 7|1@1+ (1,0) [0|1] ""  MBMU,PC
 SG_ ControlBoxFanState_22 : 8|1@1+ (1,0) [0|1] ""  MBMU,PC
 SG_ ControlBoxTempHighWarning_22 : 9|1@1+ (1,0) [0|1] ""  MBMU,PC
 SG_ PowerSWState_22 : 10|1@1+ (1,0) [0|1] ""  MBMU,PC
 SG_ FaultClearCommand_22 : 11|1@1+ (1,0) [0|1] ""  MBMU,PC

BO_ 2332753751 S2A_DryContact__23: 8 SBMU
 SG_ FireFault_Level1_23 : 0|1@1+ (1,0) [0|1] ""  MBMU,PC
 SG_ FireFault_Level2_23 : 1|1@1+ (1,0) [0|1] ""  MBMU,PC
 SG_ TempState_23 : 2|1@1+ (1,0) [0|1] ""  MBMU,PC
 SG_ FogState_23 : 3|1@1+ (1,0) [0|1] ""  MBMU,PC
 SG_ AerosolState_23 : 4|1@1+ (1,0) [0|1] ""  MBMU,PC
 SG_ AerosolFaultState_23 : 5|2@1+ (1,0) [0|3] ""  MBMU,PC
 SG_ DoorState_23 : 7|1@1+ (1,0) [0|1] ""  MBMU,PC
 SG_ ControlBoxFanState_23 : 8|1@1+ (1,0) [0|1] ""  MBMU,PC
 SG_ ControlBoxTempHighWarning_23 : 9|1@1+ (1,0) [0|1] ""  MBMU,PC
 SG_ PowerSWState_23 : 10|1@1+ (1,0) [0|1] ""  MBMU,PC
 SG_ FaultClearCommand_23 : 11|1@1+ (1,0) [0|1] ""  MBMU,PC

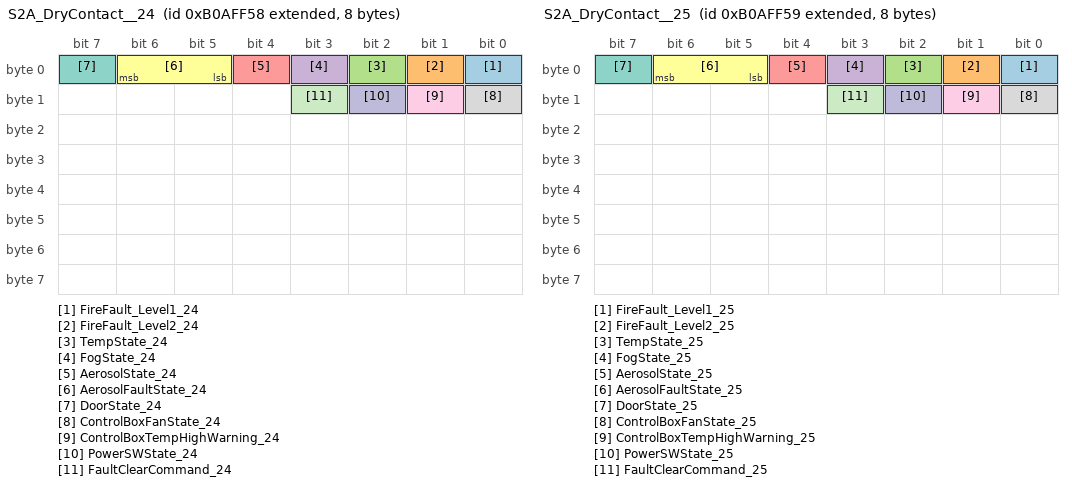
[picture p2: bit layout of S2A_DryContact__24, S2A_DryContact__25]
BO_ 2332753752 S2A_DryContact__24: 8 SBMU
 SG_ FireFault_Level1_24 : 0|1@1+ (1,0) [0|1] ""  MBMU,PC
 SG_ FireFault_Level2_24 : 1|1@1+ (1,0) [0|1] ""  MBMU,PC
 SG_ TempState_24 : 2|1@1+ (1,0) [0|1] ""  MBMU,PC
 SG_ FogState_24 : 3|1@1+ (1,0) [0|1] ""  MBMU,PC
 SG_ AerosolState_24 : 4|1@1+ (1,0) [0|1] ""  MBMU,PC
 SG_ AerosolFaultState_24 : 5|2@1+ (1,0) [0|3] ""  MBMU,PC
 SG_ DoorState_24 : 7|1@1+ (1,0) [0|1] ""  MBMU,PC
 SG_ ControlBoxFanState_24 : 8|1@1+ (1,0) [0|1] ""  MBMU,PC
 SG_ ControlBoxTempHighWarning_24 : 9|1@1+ (1,0) [0|1] ""  MBMU,PC
 SG_ PowerSWState_24 : 10|1@1+ (1,0) [0|1] ""  MBMU,PC
 SG_ FaultClearCommand_24 : 11|1@1+ (1,0) [0|1] ""  MBMU,PC

BO_ 2332753753 S2A_DryContact__25: 8 SBMU
 SG_ FireFault_Level1_25 : 0|1@1+ (1,0) [0|1] ""  MBMU,PC
 SG_ FireFault_Level2_25 : 1|1@1+ (1,0) [0|1] ""  MBMU,PC
 SG_ TempState_25 : 2|1@1+ (1,0) [0|1] ""  MBMU,PC
 SG_ FogState_25 : 3|1@1+ (1,0) [0|1] ""  MBMU,PC
 SG_ AerosolState_25 : 4|1@1+ (1,0) [0|1] ""  MBMU,PC
 SG_ AerosolFaultState_25 : 5|2@1+ (1,0) [0|3] ""  MBMU,PC
 SG_ DoorState_25 : 7|1@1+ (1,0) [0|1] ""  MBMU,PC
 SG_ ControlBoxFanState_25 : 8|1@1+ (1,0) [0|1] ""  MBMU,PC
 SG_ ControlBoxTempHighWarning_25 : 9|1@1+ (1,0) [0|1] ""  MBMU,PC
 SG_ PowerSWState_25 : 10|1@1+ (1,0) [0|1] ""  MBMU,PC
 SG_ FaultClearCommand_25 : 11|1@1+ (1,0) [0|1] ""  MBMU,PC

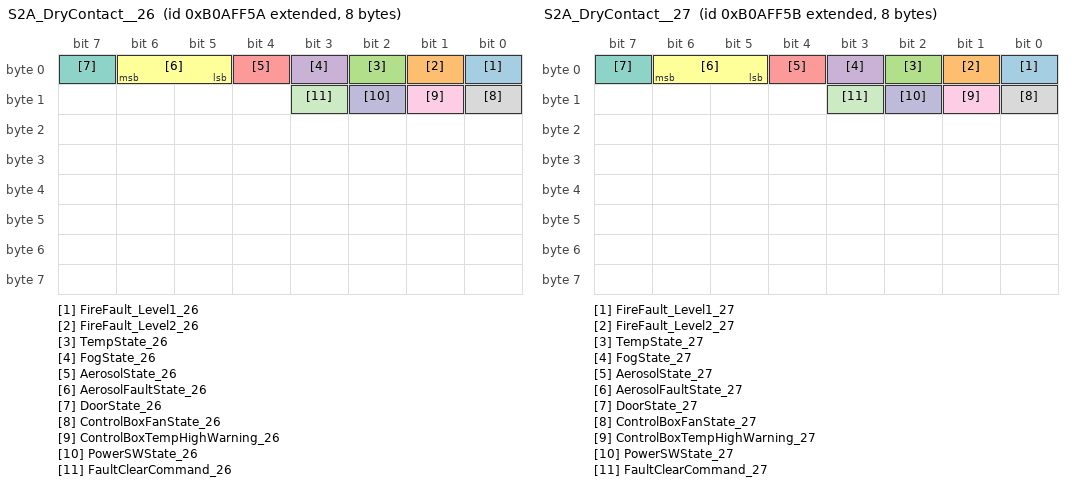
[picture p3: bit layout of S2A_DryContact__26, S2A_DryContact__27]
BO_ 2332753754 S2A_DryContact__26: 8 SBMU
 SG_ FireFault_Level1_26 : 0|1@1+ (1,0) [0|1] ""  MBMU,PC
 SG_ FireFault_Level2_26 : 1|1@1+ (1,0) [0|1] ""  MBMU,PC
 SG_ TempState_26 : 2|1@1+ (1,0) [0|1] ""  MBMU,PC
 SG_ FogState_26 : 3|1@1+ (1,0) [0|1] ""  MBMU,PC
 SG_ AerosolState_26 : 4|1@1+ (1,0) [0|1] ""  MBMU,PC
 SG_ AerosolFaultState_26 : 5|2@1+ (1,0) [0|3] ""  MBMU,PC
 SG_ DoorState_26 : 7|1@1+ (1,0) [0|1] ""  MBMU,PC
 SG_ ControlBoxFanState_26 : 8|1@1+ (1,0) [0|1] ""  MBMU,PC
 SG_ ControlBoxTempHighWarning_26 : 9|1@1+ (1,0) [0|1] ""  MBMU,PC
 SG_ PowerSWState_26 : 10|1@1+ (1,0) [0|1] ""  MBMU,PC
 SG_ FaultClearCommand_26 : 11|1@1+ (1,0) [0|1] ""  MBMU,PC

BO_ 2332753755 S2A_DryContact__27: 8 SBMU
 SG_ FireFault_Level1_27 : 0|1@1+ (1,0) [0|1] ""  MBMU,PC
 SG_ FireFault_Level2_27 : 1|1@1+ (1,0) [0|1] ""  MBMU,PC
 SG_ TempState_27 : 2|1@1+ (1,0) [0|1] ""  MBMU,PC
 SG_ FogState_27 : 3|1@1+ (1,0) [0|1] ""  MBMU,PC
 SG_ AerosolState_27 : 4|1@1+ (1,0) [0|1] ""  MBMU,PC
 SG_ AerosolFaultState_27 : 5|2@1+ (1,0) [0|3] ""  MBMU,PC
 SG_ DoorState_27 : 7|1@1+ (1,0) [0|1] ""  MBMU,PC
 SG_ ControlBoxFanState_27 : 8|1@1+ (1,0) [0|1] ""  MBMU,PC
 SG_ ControlBoxTempHighWarning_27 : 9|1@1+ (1,0) [0|1] ""  MBMU,PC
 SG_ PowerSWState_27 : 10|1@1+ (1,0) [0|1] ""  MBMU,PC
 SG_ FaultClearCommand_27 : 11|1@1+ (1,0) [0|1] ""  MBMU,PC

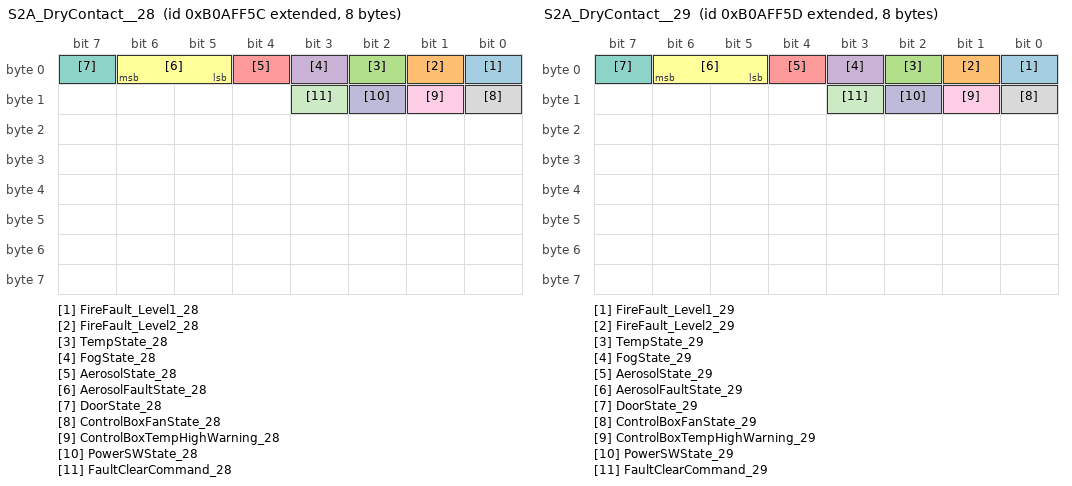
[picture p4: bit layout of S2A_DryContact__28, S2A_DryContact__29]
BO_ 2332753756 S2A_DryContact__28: 8 SBMU
 SG_ FireFault_Level1_28 : 0|1@1+ (1,0) [0|1] ""  MBMU,PC
 SG_ FireFault_Level2_28 : 1|1@1+ (1,0) [0|1] ""  MBMU,PC
 SG_ TempState_28 : 2|1@1+ (1,0) [0|1] ""  MBMU,PC
 SG_ FogState_28 : 3|1@1+ (1,0) [0|1] ""  MBMU,PC
 SG_ AerosolState_28 : 4|1@1+ (1,0) [0|1] ""  MBMU,PC
 SG_ AerosolFaultState_28 : 5|2@1+ (1,0) [0|3] ""  MBMU,PC
 SG_ DoorState_28 : 7|1@1+ (1,0) [0|1] ""  MBMU,PC
 SG_ ControlBoxFanState_28 : 8|1@1+ (1,0) [0|1] ""  MBMU,PC
 SG_ ControlBoxTempHighWarning_28 : 9|1@1+ (1,0) [0|1] ""  MBMU,PC
 SG_ PowerSWState_28 : 10|1@1+ (1,0) [0|1] ""  MBMU,PC
 SG_ FaultClearCommand_28 : 11|1@1+ (1,0) [0|1] ""  MBMU,PC

BO_ 2332753757 S2A_DryContact__29: 8 SBMU
 SG_ FireFault_Level1_29 : 0|1@1+ (1,0) [0|1] ""  MBMU,PC
 SG_ FireFault_Level2_29 : 1|1@1+ (1,0) [0|1] ""  MBMU,PC
 SG_ TempState_29 : 2|1@1+ (1,0) [0|1] ""  MBMU,PC
 SG_ FogState_29 : 3|1@1+ (1,0) [0|1] ""  MBMU,PC
 SG_ AerosolState_29 : 4|1@1+ (1,0) [0|1] ""  MBMU,PC
 SG_ AerosolFaultState_29 : 5|2@1+ (1,0) [0|3] ""  MBMU,PC
 SG_ DoorState_29 : 7|1@1+ (1,0) [0|1] ""  MBMU,PC
 SG_ ControlBoxFanState_29 : 8|1@1+ (1,0) [0|1] ""  MBMU,PC
 SG_ ControlBoxTempHighWarning_29 : 9|1@1+ (1,0) [0|1] ""  MBMU,PC
 SG_ PowerSWState_29 : 10|1@1+ (1,0) [0|1] ""  MBMU,PC
 SG_ FaultClearCommand_29 : 11|1@1+ (1,0) [0|1] ""  MBMU,PC

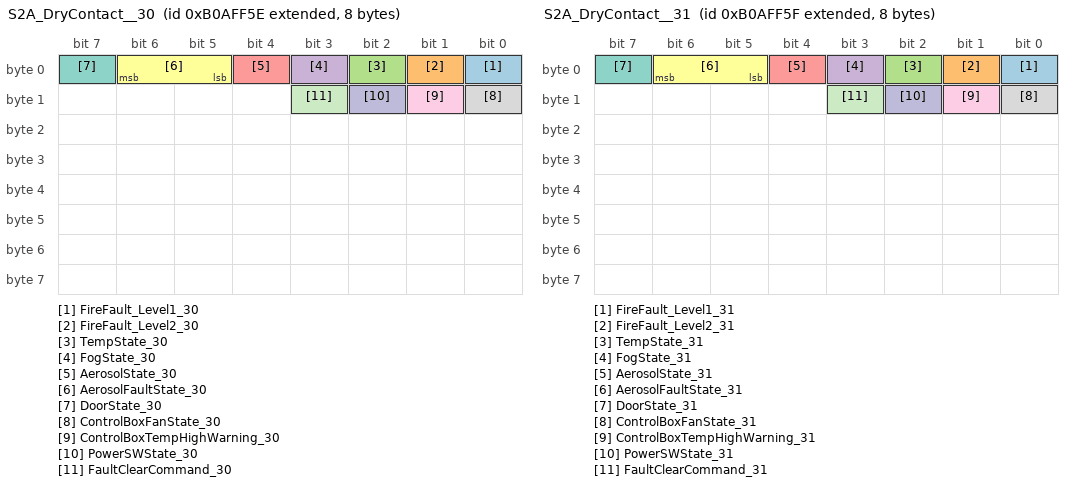
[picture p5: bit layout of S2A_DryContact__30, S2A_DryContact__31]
BO_ 2332753758 S2A_DryContact__30: 8 SBMU
 SG_ FireFault_Level1_30 : 0|1@1+ (1,0) [0|1] ""  MBMU,PC
 SG_ FireFault_Level2_30 : 1|1@1+ (1,0) [0|1] ""  MBMU,PC
 SG_ TempState_30 : 2|1@1+ (1,0) [0|1] ""  MBMU,PC
 SG_ FogState_30 : 3|1@1+ (1,0) [0|1] ""  MBMU,PC
 SG_ AerosolState_30 : 4|1@1+ (1,0) [0|1] ""  MBMU,PC
 SG_ AerosolFaultState_30 : 5|2@1+ (1,0) [0|3] ""  MBMU,PC
 SG_ DoorState_30 : 7|1@1+ (1,0) [0|1] ""  MBMU,PC
 SG_ ControlBoxFanState_30 : 8|1@1+ (1,0) [0|1] ""  MBMU,PC
 SG_ ControlBoxTempHighWarning_30 : 9|1@1+ (1,0) [0|1] ""  MBMU,PC
 SG_ PowerSWState_30 : 10|1@1+ (1,0) [0|1] ""  MBMU,PC
 SG_ FaultClearCommand_30 : 11|1@1+ (1,0) [0|1] ""  MBMU,PC

BO_ 2332753759 S2A_DryContact__31: 8 SBMU
 SG_ FireFault_Level1_31 : 0|1@1+ (1,0) [0|1] ""  MBMU,PC
 SG_ FireFault_Level2_31 : 1|1@1+ (1,0) [0|1] ""  MBMU,PC
 SG_ TempState_31 : 2|1@1+ (1,0) [0|1] ""  MBMU,PC
 SG_ FogState_31 : 3|1@1+ (1,0) [0|1] ""  MBMU,PC
 SG_ AerosolState_31 : 4|1@1+ (1,0) [0|1] ""  MBMU,PC
 SG_ AerosolFaultState_31 : 5|2@1+ (1,0) [0|3] ""  MBMU,PC
 SG_ DoorState_31 : 7|1@1+ (1,0) [0|1] ""  MBMU,PC
 SG_ ControlBoxFanState_31 : 8|1@1+ (1,0) [0|1] ""  MBMU,PC
 SG_ ControlBoxTempHighWarning_31 : 9|1@1+ (1,0) [0|1] ""  MBMU,PC
 SG_ PowerSWState_31 : 10|1@1+ (1,0) [0|1] ""  MBMU,PC
 SG_ FaultClearCommand_31 : 11|1@1+ (1,0) [0|1] ""  MBMU,PC

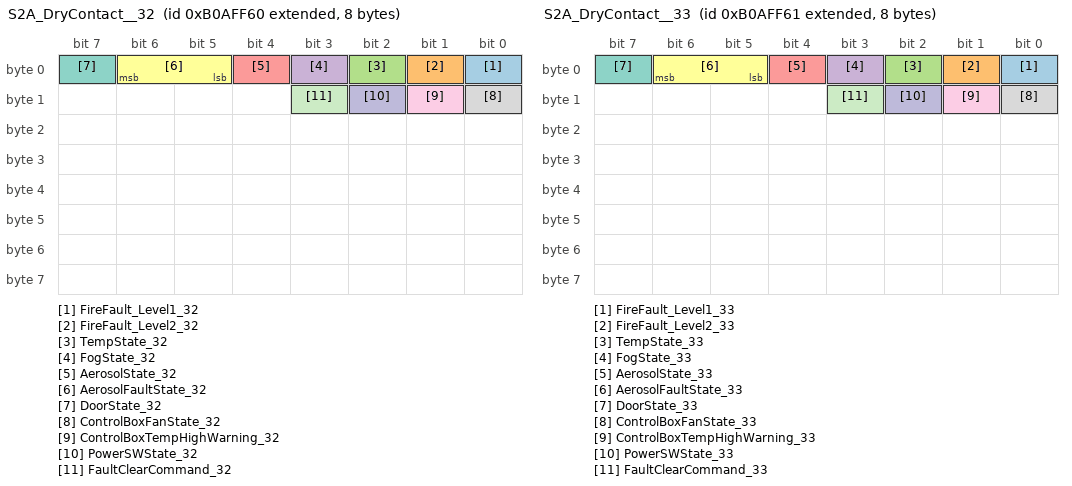
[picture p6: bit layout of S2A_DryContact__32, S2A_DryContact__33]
BO_ 2332753760 S2A_DryContact__32: 8 SBMU
 SG_ FireFault_Level1_32 : 0|1@1+ (1,0) [0|1] ""  MBMU,PC
 SG_ FireFault_Level2_32 : 1|1@1+ (1,0) [0|1] ""  MBMU,PC
 SG_ TempState_32 : 2|1@1+ (1,0) [0|1] ""  MBMU,PC
 SG_ FogState_32 : 3|1@1+ (1,0) [0|1] ""  MBMU,PC
 SG_ AerosolState_32 : 4|1@1+ (1,0) [0|1] ""  MBMU,PC
 SG_ AerosolFaultState_32 : 5|2@1+ (1,0) [0|3] ""  MBMU,PC
 SG_ DoorState_32 : 7|1@1+ (1,0) [0|1] ""  MBMU,PC
 SG_ ControlBoxFanState_32 : 8|1@1+ (1,0) [0|1] ""  MBMU,PC
 SG_ ControlBoxTempHighWarning_32 : 9|1@1+ (1,0) [0|1] ""  MBMU,PC
 SG_ PowerSWState_32 : 10|1@1+ (1,0) [0|1] ""  MBMU,PC
 SG_ FaultClearCommand_32 : 11|1@1+ (1,0) [0|1] ""  MBMU,PC

BO_ 2332753761 S2A_DryContact__33: 8 SBMU
 SG_ FireFault_Level1_33 : 0|1@1+ (1,0) [0|1] ""  MBMU,PC
 SG_ FireFault_Level2_33 : 1|1@1+ (1,0) [0|1] ""  MBMU,PC
 SG_ TempState_33 : 2|1@1+ (1,0) [0|1] ""  MBMU,PC
 SG_ FogState_33 : 3|1@1+ (1,0) [0|1] ""  MBMU,PC
 SG_ AerosolState_33 : 4|1@1+ (1,0) [0|1] ""  MBMU,PC
 SG_ AerosolFaultState_33 : 5|2@1+ (1,0) [0|3] ""  MBMU,PC
 SG_ DoorState_33 : 7|1@1+ (1,0) [0|1] ""  MBMU,PC
 SG_ ControlBoxFanState_33 : 8|1@1+ (1,0) [0|1] ""  MBMU,PC
 SG_ ControlBoxTempHighWarning_33 : 9|1@1+ (1,0) [0|1] ""  MBMU,PC
 SG_ PowerSWState_33 : 10|1@1+ (1,0) [0|1] ""  MBMU,PC
 SG_ FaultClearCommand_33 : 11|1@1+ (1,0) [0|1] ""  MBMU,PC

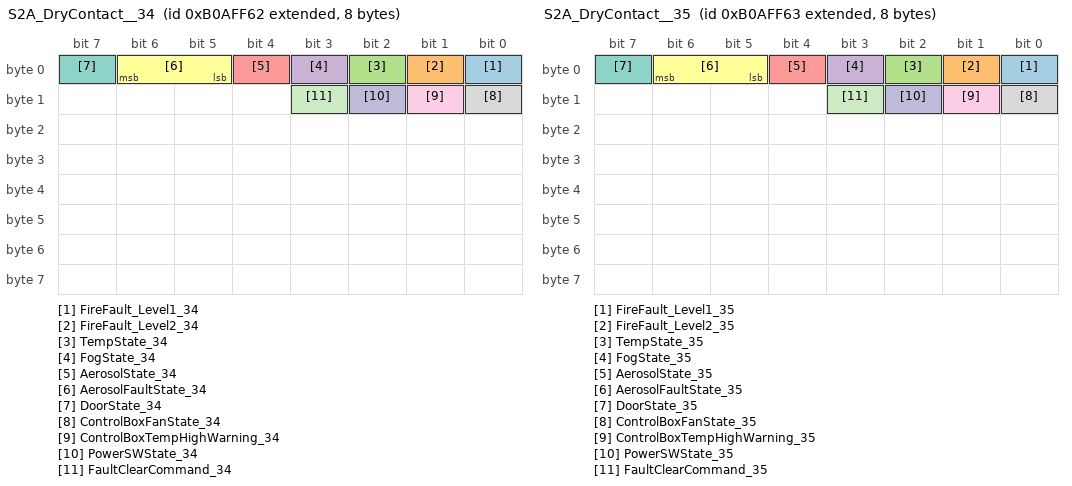
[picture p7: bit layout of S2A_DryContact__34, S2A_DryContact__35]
BO_ 2332753762 S2A_DryContact__34: 8 SBMU
 SG_ FireFault_Level1_34 : 0|1@1+ (1,0) [0|1] ""  MBMU,PC
 SG_ FireFault_Level2_34 : 1|1@1+ (1,0) [0|1] ""  MBMU,PC
 SG_ TempState_34 : 2|1@1+ (1,0) [0|1] ""  MBMU,PC
 SG_ FogState_34 : 3|1@1+ (1,0) [0|1] ""  MBMU,PC
 SG_ AerosolState_34 : 4|1@1+ (1,0) [0|1] ""  MBMU,PC
 SG_ AerosolFaultState_34 : 5|2@1+ (1,0) [0|3] ""  MBMU,PC
 SG_ DoorState_34 : 7|1@1+ (1,0) [0|1] ""  MBMU,PC
 SG_ ControlBoxFanState_34 : 8|1@1+ (1,0) [0|1] ""  MBMU,PC
 SG_ ControlBoxTempHighWarning_34 : 9|1@1+ (1,0) [0|1] ""  MBMU,PC
 SG_ PowerSWState_34 : 10|1@1+ (1,0) [0|1] ""  MBMU,PC
 SG_ FaultClearCommand_34 : 11|1@1+ (1,0) [0|1] ""  MBMU,PC

BO_ 2332753763 S2A_DryContact__35: 8 SBMU
 SG_ FireFault_Level1_35 : 0|1@1+ (1,0) [0|1] ""  MBMU,PC
 SG_ FireFault_Level2_35 : 1|1@1+ (1,0) [0|1] ""  MBMU,PC
 SG_ TempState_35 : 2|1@1+ (1,0) [0|1] ""  MBMU,PC
 SG_ FogState_35 : 3|1@1+ (1,0) [0|1] ""  MBMU,PC
 SG_ AerosolState_35 : 4|1@1+ (1,0) [0|1] ""  MBMU,PC
 SG_ AerosolFaultState_35 : 5|2@1+ (1,0) [0|3] ""  MBMU,PC
 SG_ DoorState_35 : 7|1@1+ (1,0) [0|1] ""  MBMU,PC
 SG_ ControlBoxFanState_35 : 8|1@1+ (1,0) [0|1] ""  MBMU,PC
 SG_ ControlBoxTempHighWarning_35 : 9|1@1+ (1,0) [0|1] ""  MBMU,PC
 SG_ PowerSWState_35 : 10|1@1+ (1,0) [0|1] ""  MBMU,PC
 SG_ FaultClearCommand_35 : 11|1@1+ (1,0) [0|1] ""  MBMU,PC

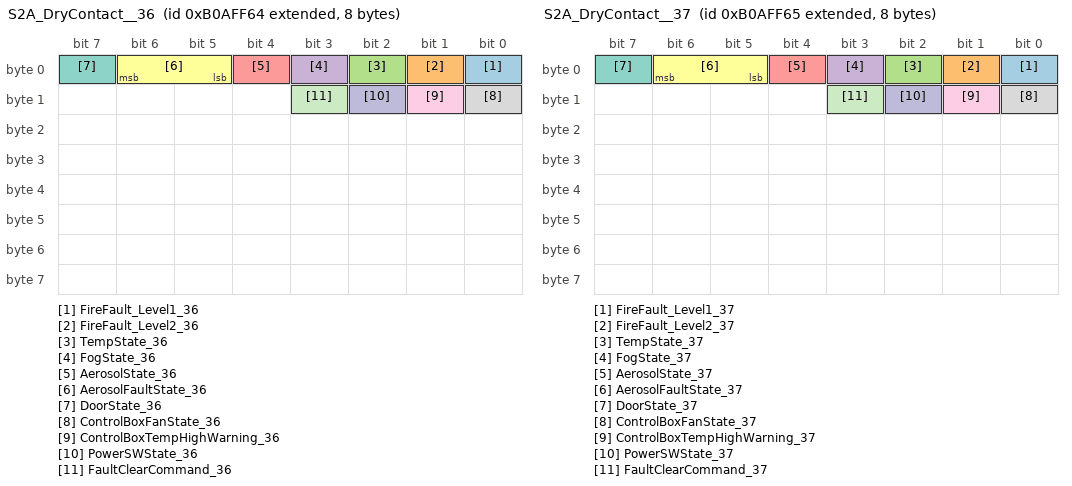
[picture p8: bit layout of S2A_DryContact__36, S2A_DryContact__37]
BO_ 2332753764 S2A_DryContact__36: 8 SBMU
 SG_ FireFault_Level1_36 : 0|1@1+ (1,0) [0|1] ""  MBMU,PC
 SG_ FireFault_Level2_36 : 1|1@1+ (1,0) [0|1] ""  MBMU,PC
 SG_ TempState_36 : 2|1@1+ (1,0) [0|1] ""  MBMU,PC
 SG_ FogState_36 : 3|1@1+ (1,0) [0|1] ""  MBMU,PC
 SG_ AerosolState_36 : 4|1@1+ (1,0) [0|1] ""  MBMU,PC
 SG_ AerosolFaultState_36 : 5|2@1+ (1,0) [0|3] ""  MBMU,PC
 SG_ DoorState_36 : 7|1@1+ (1,0) [0|1] ""  MBMU,PC
 SG_ ControlBoxFanState_36 : 8|1@1+ (1,0) [0|1] ""  MBMU,PC
 SG_ ControlBoxTempHighWarning_36 : 9|1@1+ (1,0) [0|1] ""  MBMU,PC
 SG_ PowerSWState_36 : 10|1@1+ (1,0) [0|1] ""  MBMU,PC
 SG_ FaultClearCommand_36 : 11|1@1+ (1,0) [0|1] ""  MBMU,PC

BO_ 2332753765 S2A_DryContact__37: 8 SBMU
 SG_ FireFault_Level1_37 : 0|1@1+ (1,0) [0|1] ""  MBMU,PC
 SG_ FireFault_Level2_37 : 1|1@1+ (1,0) [0|1] ""  MBMU,PC
 SG_ TempState_37 : 2|1@1+ (1,0) [0|1] ""  MBMU,PC
 SG_ FogState_37 : 3|1@1+ (1,0) [0|1] ""  MBMU,PC
 SG_ AerosolState_37 : 4|1@1+ (1,0) [0|1] ""  MBMU,PC
 SG_ AerosolFaultState_37 : 5|2@1+ (1,0) [0|3] ""  MBMU,PC
 SG_ DoorState_37 : 7|1@1+ (1,0) [0|1] ""  MBMU,PC
 SG_ ControlBoxFanState_37 : 8|1@1+ (1,0) [0|1] ""  MBMU,PC
 SG_ ControlBoxTempHighWarning_37 : 9|1@1+ (1,0) [0|1] ""  MBMU,PC
 SG_ PowerSWState_37 : 10|1@1+ (1,0) [0|1] ""  MBMU,PC
 SG_ FaultClearCommand_37 : 11|1@1+ (1,0) [0|1] ""  MBMU,PC

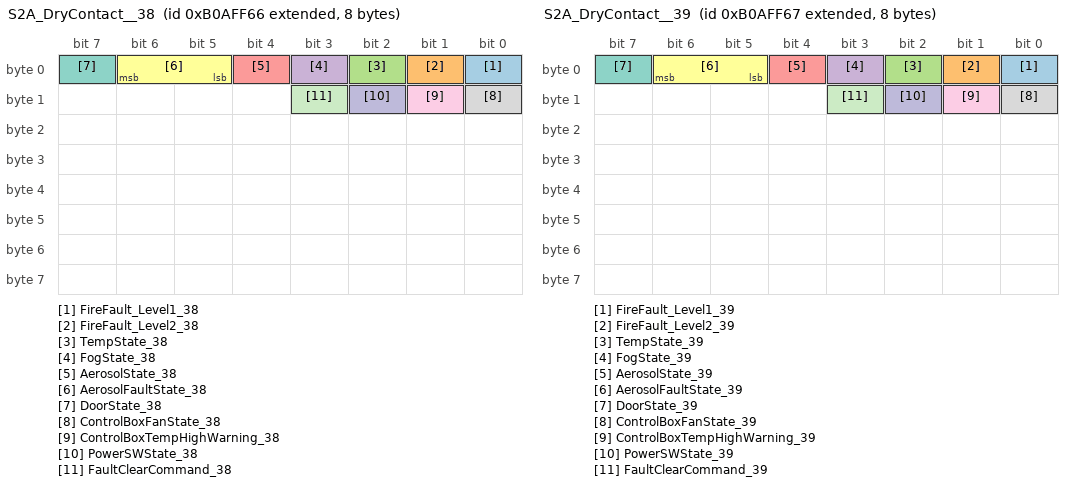
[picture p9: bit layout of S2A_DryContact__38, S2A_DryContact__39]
BO_ 2332753766 S2A_DryContact__38: 8 SBMU
 SG_ FireFault_Level1_38 : 0|1@1+ (1,0) [0|1] ""  MBMU,PC
 SG_ FireFault_Level2_38 : 1|1@1+ (1,0) [0|1] ""  MBMU,PC
 SG_ TempState_38 : 2|1@1+ (1,0) [0|1] ""  MBMU,PC
 SG_ FogState_38 : 3|1@1+ (1,0) [0|1] ""  MBMU,PC
 SG_ AerosolState_38 : 4|1@1+ (1,0) [0|1] ""  MBMU,PC
 SG_ AerosolFaultState_38 : 5|2@1+ (1,0) [0|3] ""  MBMU,PC
 SG_ DoorState_38 : 7|1@1+ (1,0) [0|1] ""  MBMU,PC
 SG_ ControlBoxFanState_38 : 8|1@1+ (1,0) [0|1] ""  MBMU,PC
 SG_ ControlBoxTempHighWarning_38 : 9|1@1+ (1,0) [0|1] ""  MBMU,PC
 SG_ PowerSWState_38 : 10|1@1+ (1,0) [0|1] ""  MBMU,PC
 SG_ FaultClearCommand_38 : 11|1@1+ (1,0) [0|1] ""  MBMU,PC

BO_ 2332753767 S2A_DryContact__39: 8 SBMU
 SG_ FireFault_Level1_39 : 0|1@1+ (1,0) [0|1] ""  MBMU,PC
 SG_ FireFault_Level2_39 : 1|1@1+ (1,0) [0|1] ""  MBMU,PC
 SG_ TempState_39 : 2|1@1+ (1,0) [0|1] ""  MBMU,PC
 SG_ FogState_39 : 3|1@1+ (1,0) [0|1] ""  MBMU,PC
 SG_ AerosolState_39 : 4|1@1+ (1,0) [0|1] ""  MBMU,PC
 SG_ AerosolFaultState_39 : 5|2@1+ (1,0) [0|3] ""  MBMU,PC
 SG_ DoorState_39 : 7|1@1+ (1,0) [0|1] ""  MBMU,PC
 SG_ ControlBoxFanState_39 : 8|1@1+ (1,0) [0|1] ""  MBMU,PC
 SG_ ControlBoxTempHighWarning_39 : 9|1@1+ (1,0) [0|1] ""  MBMU,PC
 SG_ PowerSWState_39 : 10|1@1+ (1,0) [0|1] ""  MBMU,PC
 SG_ FaultClearCommand_39 : 11|1@1+ (1,0) [0|1] ""  MBMU,PC

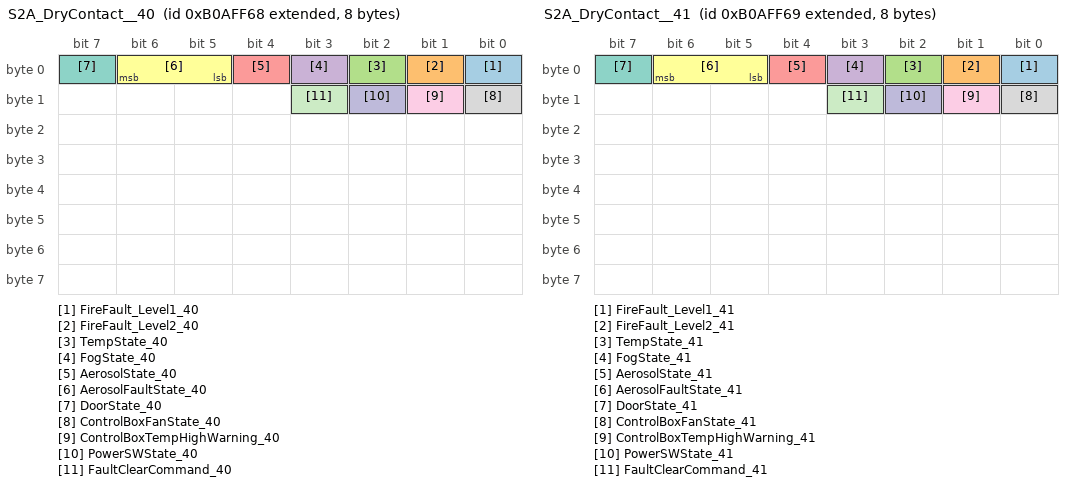
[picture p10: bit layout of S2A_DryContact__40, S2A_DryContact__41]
BO_ 2332753768 S2A_DryContact__40: 8 SBMU
 SG_ FireFault_Level1_40 : 0|1@1+ (1,0) [0|1] ""  MBMU,PC
 SG_ FireFault_Level2_40 : 1|1@1+ (1,0) [0|1] ""  MBMU,PC
 SG_ TempState_40 : 2|1@1+ (1,0) [0|1] ""  MBMU,PC
 SG_ FogState_40 : 3|1@1+ (1,0) [0|1] ""  MBMU,PC
 SG_ AerosolState_40 : 4|1@1+ (1,0) [0|1] ""  MBMU,PC
 SG_ AerosolFaultState_40 : 5|2@1+ (1,0) [0|3] ""  MBMU,PC
 SG_ DoorState_40 : 7|1@1+ (1,0) [0|1] ""  MBMU,PC
 SG_ ControlBoxFanState_40 : 8|1@1+ (1,0) [0|1] ""  MBMU,PC
 SG_ ControlBoxTempHighWarning_40 : 9|1@1+ (1,0) [0|1] ""  MBMU,PC
 SG_ PowerSWState_40 : 10|1@1+ (1,0) [0|1] ""  MBMU,PC
 SG_ FaultClearCommand_40 : 11|1@1+ (1,0) [0|1] ""  MBMU,PC

BO_ 2332753769 S2A_DryContact__41: 8 SBMU
 SG_ FireFault_Level1_41 : 0|1@1+ (1,0) [0|1] ""  MBMU,PC
 SG_ FireFault_Level2_41 : 1|1@1+ (1,0) [0|1] ""  MBMU,PC
 SG_ TempState_41 : 2|1@1+ (1,0) [0|1] ""  MBMU,PC
 SG_ FogState_41 : 3|1@1+ (1,0) [0|1] ""  MBMU,PC
 SG_ AerosolState_41 : 4|1@1+ (1,0) [0|1] ""  MBMU,PC
 SG_ AerosolFaultState_41 : 5|2@1+ (1,0) [0|3] ""  MBMU,PC
 SG_ DoorState_41 : 7|1@1+ (1,0) [0|1] ""  MBMU,PC
 SG_ ControlBoxFanState_41 : 8|1@1+ (1,0) [0|1] ""  MBMU,PC
 SG_ ControlBoxTempHighWarning_41 : 9|1@1+ (1,0) [0|1] ""  MBMU,PC
 SG_ PowerSWState_41 : 10|1@1+ (1,0) [0|1] ""  MBMU,PC
 SG_ FaultClearCommand_41 : 11|1@1+ (1,0) [0|1] ""  MBMU,PC

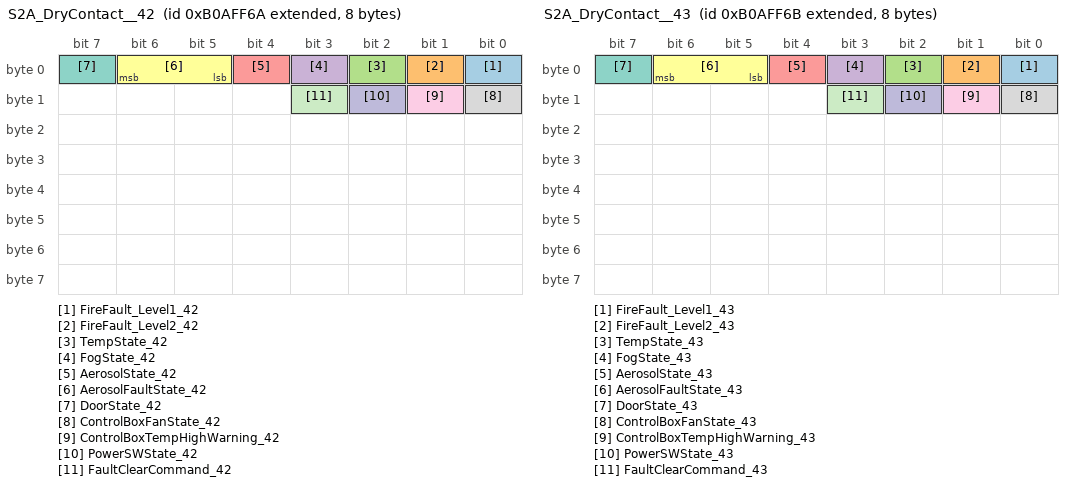
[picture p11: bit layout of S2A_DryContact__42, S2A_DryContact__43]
BO_ 2332753770 S2A_DryContact__42: 8 SBMU
 SG_ FireFault_Level1_42 : 0|1@1+ (1,0) [0|1] ""  MBMU,PC
 SG_ FireFault_Level2_42 : 1|1@1+ (1,0) [0|1] ""  MBMU,PC
 SG_ TempState_42 : 2|1@1+ (1,0) [0|1] ""  MBMU,PC
 SG_ FogState_42 : 3|1@1+ (1,0) [0|1] ""  MBMU,PC
 SG_ AerosolState_42 : 4|1@1+ (1,0) [0|1] ""  MBMU,PC
 SG_ AerosolFaultState_42 : 5|2@1+ (1,0) [0|3] ""  MBMU,PC
 SG_ DoorState_42 : 7|1@1+ (1,0) [0|1] ""  MBMU,PC
 SG_ ControlBoxFanState_42 : 8|1@1+ (1,0) [0|1] ""  MBMU,PC
 SG_ ControlBoxTempHighWarning_42 : 9|1@1+ (1,0) [0|1] ""  MBMU,PC
 SG_ PowerSWState_42 : 10|1@1+ (1,0) [0|1] ""  MBMU,PC
 SG_ FaultClearCommand_42 : 11|1@1+ (1,0) [0|1] ""  MBMU,PC

BO_ 2332753771 S2A_DryContact__43: 8 SBMU
 SG_ FireFault_Level1_43 : 0|1@1+ (1,0) [0|1] ""  MBMU,PC
 SG_ FireFault_Level2_43 : 1|1@1+ (1,0) [0|1] ""  MBMU,PC
 SG_ TempState_43 : 2|1@1+ (1,0) [0|1] ""  MBMU,PC
 SG_ FogState_43 : 3|1@1+ (1,0) [0|1] ""  MBMU,PC
 SG_ AerosolState_43 : 4|1@1+ (1,0) [0|1] ""  MBMU,PC
 SG_ AerosolFaultState_43 : 5|2@1+ (1,0) [0|3] ""  MBMU,PC
 SG_ DoorState_43 : 7|1@1+ (1,0) [0|1] ""  MBMU,PC
 SG_ ControlBoxFanState_43 : 8|1@1+ (1,0) [0|1] ""  MBMU,PC
 SG_ ControlBoxTempHighWarning_43 : 9|1@1+ (1,0) [0|1] ""  MBMU,PC
 SG_ PowerSWState_43 : 10|1@1+ (1,0) [0|1] ""  MBMU,PC
 SG_ FaultClearCommand_43 : 11|1@1+ (1,0) [0|1] ""  MBMU,PC

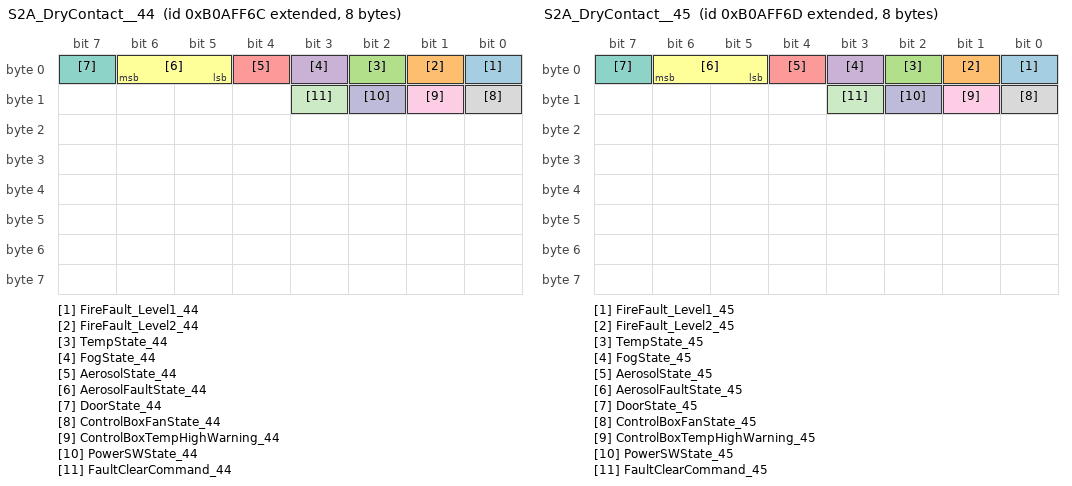
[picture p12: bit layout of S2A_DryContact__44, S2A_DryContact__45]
BO_ 2332753772 S2A_DryContact__44: 8 SBMU
 SG_ FireFault_Level1_44 : 0|1@1+ (1,0) [0|1] ""  MBMU,PC
 SG_ FireFault_Level2_44 : 1|1@1+ (1,0) [0|1] ""  MBMU,PC
 SG_ TempState_44 : 2|1@1+ (1,0) [0|1] ""  MBMU,PC
 SG_ FogState_44 : 3|1@1+ (1,0) [0|1] ""  MBMU,PC
 SG_ AerosolState_44 : 4|1@1+ (1,0) [0|1] ""  MBMU,PC
 SG_ AerosolFaultState_44 : 5|2@1+ (1,0) [0|3] ""  MBMU,PC
 SG_ DoorState_44 : 7|1@1+ (1,0) [0|1] ""  MBMU,PC
 SG_ ControlBoxFanState_44 : 8|1@1+ (1,0) [0|1] ""  MBMU,PC
 SG_ ControlBoxTempHighWarning_44 : 9|1@1+ (1,0) [0|1] ""  MBMU,PC
 SG_ PowerSWState_44 : 10|1@1+ (1,0) [0|1] ""  MBMU,PC
 SG_ FaultClearCommand_44 : 11|1@1+ (1,0) [0|1] ""  MBMU,PC

BO_ 2332753773 S2A_DryContact__45: 8 SBMU
 SG_ FireFault_Level1_45 : 0|1@1+ (1,0) [0|1] ""  MBMU,PC
 SG_ FireFault_Level2_45 : 1|1@1+ (1,0) [0|1] ""  MBMU,PC
 SG_ TempState_45 : 2|1@1+ (1,0) [0|1] ""  MBMU,PC
 SG_ FogState_45 : 3|1@1+ (1,0) [0|1] ""  MBMU,PC
 SG_ AerosolState_45 : 4|1@1+ (1,0) [0|1] ""  MBMU,PC
 SG_ AerosolFaultState_45 : 5|2@1+ (1,0) [0|3] ""  MBMU,PC
 SG_ DoorState_45 : 7|1@1+ (1,0) [0|1] ""  MBMU,PC
 SG_ ControlBoxFanState_45 : 8|1@1+ (1,0) [0|1] ""  MBMU,PC
 SG_ ControlBoxTempHighWarning_45 : 9|1@1+ (1,0) [0|1] ""  MBMU,PC
 SG_ PowerSWState_45 : 10|1@1+ (1,0) [0|1] ""  MBMU,PC
 SG_ FaultClearCommand_45 : 11|1@1+ (1,0) [0|1] ""  MBMU,PC

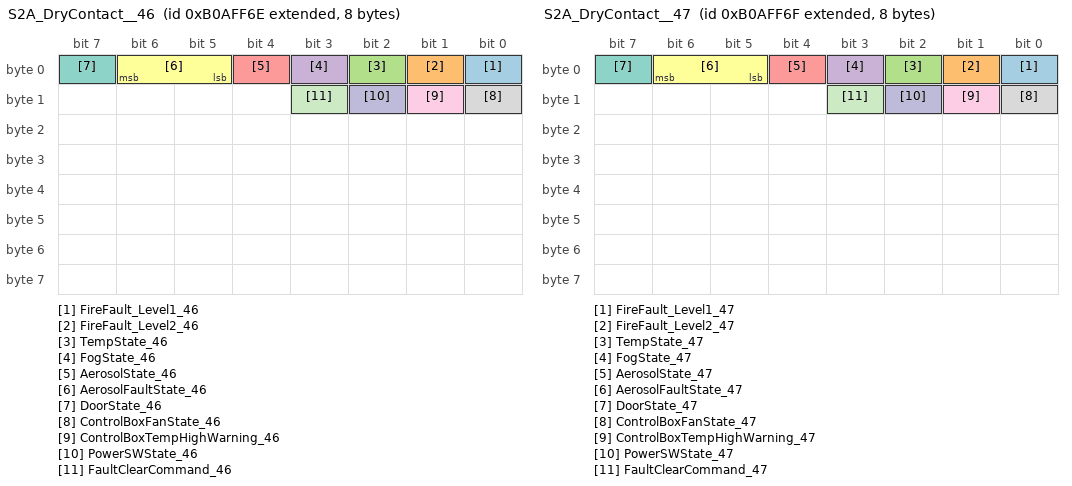
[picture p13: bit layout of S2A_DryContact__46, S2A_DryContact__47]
BO_ 2332753774 S2A_DryContact__46: 8 SBMU
 SG_ FireFault_Level1_46 : 0|1@1+ (1,0) [0|1] ""  MBMU,PC
 SG_ FireFault_Level2_46 : 1|1@1+ (1,0) [0|1] ""  MBMU,PC
 SG_ TempState_46 : 2|1@1+ (1,0) [0|1] ""  MBMU,PC
 SG_ FogState_46 : 3|1@1+ (1,0) [0|1] ""  MBMU,PC
 SG_ AerosolState_46 : 4|1@1+ (1,0) [0|1] ""  MBMU,PC
 SG_ AerosolFaultState_46 : 5|2@1+ (1,0) [0|3] ""  MBMU,PC
 SG_ DoorState_46 : 7|1@1+ (1,0) [0|1] ""  MBMU,PC
 SG_ ControlBoxFanState_46 : 8|1@1+ (1,0) [0|1] ""  MBMU,PC
 SG_ ControlBoxTempHighWarning_46 : 9|1@1+ (1,0) [0|1] ""  MBMU,PC
 SG_ PowerSWState_46 : 10|1@1+ (1,0) [0|1] ""  MBMU,PC
 SG_ FaultClearCommand_46 : 11|1@1+ (1,0) [0|1] ""  MBMU,PC

BO_ 2332753775 S2A_DryContact__47: 8 SBMU
 SG_ FireFault_Level1_47 : 0|1@1+ (1,0) [0|1] ""  MBMU,PC
 SG_ FireFault_Level2_47 : 1|1@1+ (1,0) [0|1] ""  MBMU,PC
 SG_ TempState_47 : 2|1@1+ (1,0) [0|1] ""  MBMU,PC
 SG_ FogState_47 : 3|1@1+ (1,0) [0|1] ""  MBMU,PC
 SG_ AerosolState_47 : 4|1@1+ (1,0) [0|1] ""  MBMU,PC
 SG_ AerosolFaultState_47 : 5|2@1+ (1,0) [0|3] ""  MBMU,PC
 SG_ DoorState_47 : 7|1@1+ (1,0) [0|1] ""  MBMU,PC
 SG_ ControlBoxFanState_47 : 8|1@1+ (1,0) [0|1] ""  MBMU,PC
 SG_ ControlBoxTempHighWarning_47 : 9|1@1+ (1,0) [0|1] ""  MBMU,PC
 SG_ PowerSWState_47 : 10|1@1+ (1,0) [0|1] ""  MBMU,PC
 SG_ FaultClearCommand_47 : 11|1@1+ (1,0) [0|1] ""  MBMU,PC

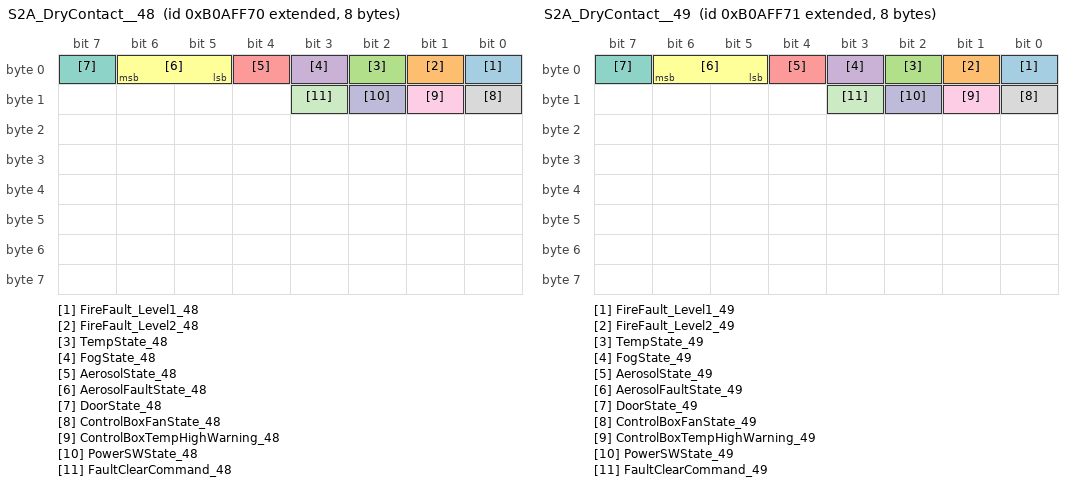
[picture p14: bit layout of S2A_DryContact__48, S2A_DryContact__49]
BO_ 2332753776 S2A_DryContact__48: 8 SBMU
 SG_ FireFault_Level1_48 : 0|1@1+ (1,0) [0|1] ""  MBMU,PC
 SG_ FireFault_Level2_48 : 1|1@1+ (1,0) [0|1] ""  MBMU,PC
 SG_ TempState_48 : 2|1@1+ (1,0) [0|1] ""  MBMU,PC
 SG_ FogState_48 : 3|1@1+ (1,0) [0|1] ""  MBMU,PC
 SG_ AerosolState_48 : 4|1@1+ (1,0) [0|1] ""  MBMU,PC
 SG_ AerosolFaultState_48 : 5|2@1+ (1,0) [0|3] ""  MBMU,PC
 SG_ DoorState_48 : 7|1@1+ (1,0) [0|1] ""  MBMU,PC
 SG_ ControlBoxFanState_48 : 8|1@1+ (1,0) [0|1] ""  MBMU,PC
 SG_ ControlBoxTempHighWarning_48 : 9|1@1+ (1,0) [0|1] ""  MBMU,PC
 SG_ PowerSWState_48 : 10|1@1+ (1,0) [0|1] ""  MBMU,PC
 SG_ FaultClearCommand_48 : 11|1@1+ (1,0) [0|1] ""  MBMU,PC

BO_ 2332753777 S2A_DryContact__49: 8 SBMU
 SG_ FireFault_Level1_49 : 0|1@1+ (1,0) [0|1] ""  MBMU,PC
 SG_ FireFault_Level2_49 : 1|1@1+ (1,0) [0|1] ""  MBMU,PC
 SG_ TempState_49 : 2|1@1+ (1,0) [0|1] ""  MBMU,PC
 SG_ FogState_49 : 3|1@1+ (1,0) [0|1] ""  MBMU,PC
 SG_ AerosolState_49 : 4|1@1+ (1,0) [0|1] ""  MBMU,PC
 SG_ AerosolFaultState_49 : 5|2@1+ (1,0) [0|3] ""  MBMU,PC
 SG_ DoorState_49 : 7|1@1+ (1,0) [0|1] ""  MBMU,PC
 SG_ ControlBoxFanState_49 : 8|1@1+ (1,0) [0|1] ""  MBMU,PC
 SG_ ControlBoxTempHighWarning_49 : 9|1@1+ (1,0) [0|1] ""  MBMU,PC
 SG_ PowerSWState_49 : 10|1@1+ (1,0) [0|1] ""  MBMU,PC
 SG_ FaultClearCommand_49 : 11|1@1+ (1,0) [0|1] ""  MBMU,PC

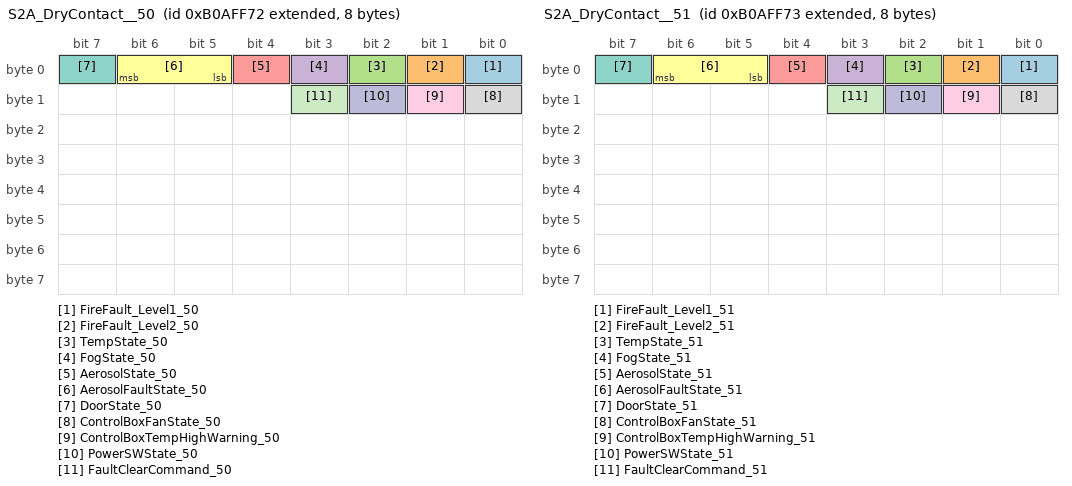
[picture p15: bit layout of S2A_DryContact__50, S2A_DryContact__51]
BO_ 2332753778 S2A_DryContact__50: 8 SBMU
 SG_ FireFault_Level1_50 : 0|1@1+ (1,0) [0|1] ""  MBMU,PC
 SG_ FireFault_Level2_50 : 1|1@1+ (1,0) [0|1] ""  MBMU,PC
 SG_ TempState_50 : 2|1@1+ (1,0) [0|1] ""  MBMU,PC
 SG_ FogState_50 : 3|1@1+ (1,0) [0|1] ""  MBMU,PC
 SG_ AerosolState_50 : 4|1@1+ (1,0) [0|1] ""  MBMU,PC
 SG_ AerosolFaultState_50 : 5|2@1+ (1,0) [0|3] ""  MBMU,PC
 SG_ DoorState_50 : 7|1@1+ (1,0) [0|1] ""  MBMU,PC
 SG_ ControlBoxFanState_50 : 8|1@1+ (1,0) [0|1] ""  MBMU,PC
 SG_ ControlBoxTempHighWarning_50 : 9|1@1+ (1,0) [0|1] ""  MBMU,PC
 SG_ PowerSWState_50 : 10|1@1+ (1,0) [0|1] ""  MBMU,PC
 SG_ FaultClearCommand_50 : 11|1@1+ (1,0) [0|1] ""  MBMU,PC

BO_ 2332753779 S2A_DryContact__51: 8 SBMU
 SG_ FireFault_Level1_51 : 0|1@1+ (1,0) [0|1] ""  MBMU,PC
 SG_ FireFault_Level2_51 : 1|1@1+ (1,0) [0|1] ""  MBMU,PC
 SG_ TempState_51 : 2|1@1+ (1,0) [0|1] ""  MBMU,PC
 SG_ FogState_51 : 3|1@1+ (1,0) [0|1] ""  MBMU,PC
 SG_ AerosolState_51 : 4|1@1+ (1,0) [0|1] ""  MBMU,PC
 SG_ AerosolFaultState_51 : 5|2@1+ (1,0) [0|3] ""  MBMU,PC
 SG_ DoorState_51 : 7|1@1+ (1,0) [0|1] ""  MBMU,PC
 SG_ ControlBoxFanState_51 : 8|1@1+ (1,0) [0|1] ""  MBMU,PC
 SG_ ControlBoxTempHighWarning_51 : 9|1@1+ (1,0) [0|1] ""  MBMU,PC
 SG_ PowerSWState_51 : 10|1@1+ (1,0) [0|1] ""  MBMU,PC
 SG_ FaultClearCommand_51 : 11|1@1+ (1,0) [0|1] ""  MBMU,PC

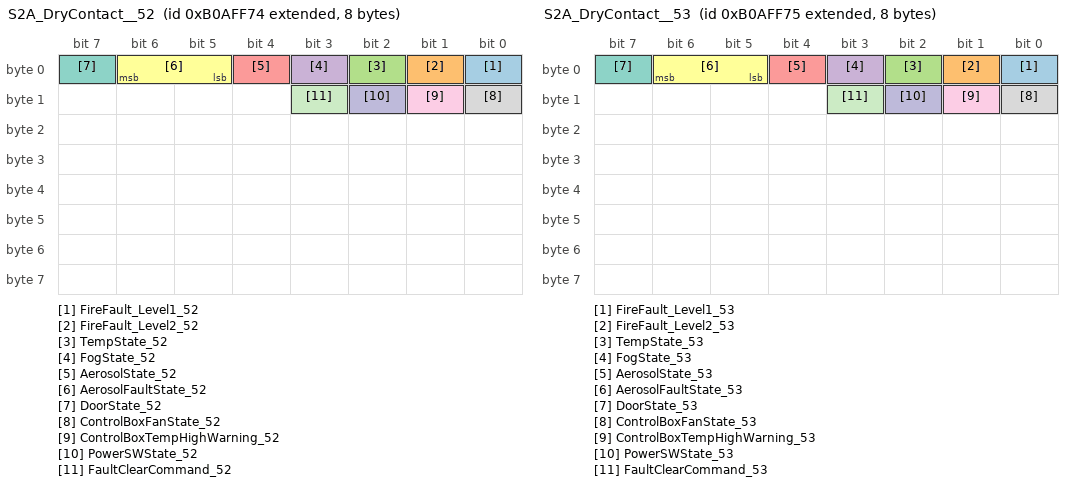
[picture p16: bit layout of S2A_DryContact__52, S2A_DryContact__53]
BO_ 2332753780 S2A_DryContact__52: 8 SBMU
 SG_ FireFault_Level1_52 : 0|1@1+ (1,0) [0|1] ""  MBMU,PC
 SG_ FireFault_Level2_52 : 1|1@1+ (1,0) [0|1] ""  MBMU,PC
 SG_ TempState_52 : 2|1@1+ (1,0) [0|1] ""  MBMU,PC
 SG_ FogState_52 : 3|1@1+ (1,0) [0|1] ""  MBMU,PC
 SG_ AerosolState_52 : 4|1@1+ (1,0) [0|1] ""  MBMU,PC
 SG_ AerosolFaultState_52 : 5|2@1+ (1,0) [0|3] ""  MBMU,PC
 SG_ DoorState_52 : 7|1@1+ (1,0) [0|1] ""  MBMU,PC
 SG_ ControlBoxFanState_52 : 8|1@1+ (1,0) [0|1] ""  MBMU,PC
 SG_ ControlBoxTempHighWarning_52 : 9|1@1+ (1,0) [0|1] ""  MBMU,PC
 SG_ PowerSWState_52 : 10|1@1+ (1,0) [0|1] ""  MBMU,PC
 SG_ FaultClearCommand_52 : 11|1@1+ (1,0) [0|1] ""  MBMU,PC

BO_ 2332753781 S2A_DryContact__53: 8 SBMU
 SG_ FireFault_Level1_53 : 0|1@1+ (1,0) [0|1] ""  MBMU,PC
 SG_ FireFault_Level2_53 : 1|1@1+ (1,0) [0|1] ""  MBMU,PC
 SG_ TempState_53 : 2|1@1+ (1,0) [0|1] ""  MBMU,PC
 SG_ FogState_53 : 3|1@1+ (1,0) [0|1] ""  MBMU,PC
 SG_ AerosolState_53 : 4|1@1+ (1,0) [0|1] ""  MBMU,PC
 SG_ AerosolFaultState_53 : 5|2@1+ (1,0) [0|3] ""  MBMU,PC
 SG_ DoorState_53 : 7|1@1+ (1,0) [0|1] ""  MBMU,PC
 SG_ ControlBoxFanState_53 : 8|1@1+ (1,0) [0|1] ""  MBMU,PC
 SG_ ControlBoxTempHighWarning_53 : 9|1@1+ (1,0) [0|1] ""  MBMU,PC
 SG_ PowerSWState_53 : 10|1@1+ (1,0) [0|1] ""  MBMU,PC
 SG_ FaultClearCommand_53 : 11|1@1+ (1,0) [0|1] ""  MBMU,PC

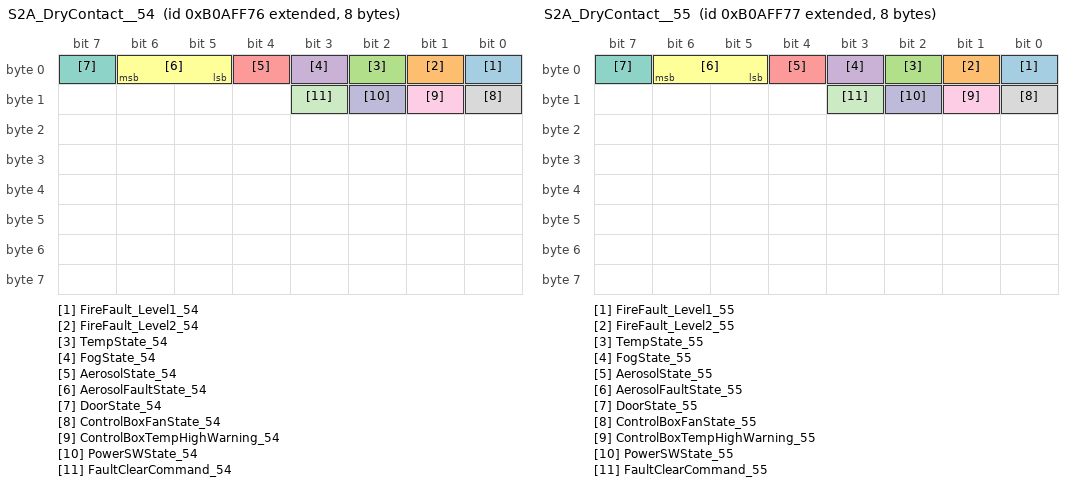
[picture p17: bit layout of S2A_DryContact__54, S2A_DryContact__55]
BO_ 2332753782 S2A_DryContact__54: 8 SBMU
 SG_ FireFault_Level1_54 : 0|1@1+ (1,0) [0|1] ""  MBMU,PC
 SG_ FireFault_Level2_54 : 1|1@1+ (1,0) [0|1] ""  MBMU,PC
 SG_ TempState_54 : 2|1@1+ (1,0) [0|1] ""  MBMU,PC
 SG_ FogState_54 : 3|1@1+ (1,0) [0|1] ""  MBMU,PC
 SG_ AerosolState_54 : 4|1@1+ (1,0) [0|1] ""  MBMU,PC
 SG_ AerosolFaultState_54 : 5|2@1+ (1,0) [0|3] ""  MBMU,PC
 SG_ DoorState_54 : 7|1@1+ (1,0) [0|1] ""  MBMU,PC
 SG_ ControlBoxFanState_54 : 8|1@1+ (1,0) [0|1] ""  MBMU,PC
 SG_ ControlBoxTempHighWarning_54 : 9|1@1+ (1,0) [0|1] ""  MBMU,PC
 SG_ PowerSWState_54 : 10|1@1+ (1,0) [0|1] ""  MBMU,PC
 SG_ FaultClearCommand_54 : 11|1@1+ (1,0) [0|1] ""  MBMU,PC

BO_ 2332753783 S2A_DryContact__55: 8 SBMU
 SG_ FireFault_Level1_55 : 0|1@1+ (1,0) [0|1] ""  MBMU,PC
 SG_ FireFault_Level2_55 : 1|1@1+ (1,0) [0|1] ""  MBMU,PC
 SG_ TempState_55 : 2|1@1+ (1,0) [0|1] ""  MBMU,PC
 SG_ FogState_55 : 3|1@1+ (1,0) [0|1] ""  MBMU,PC
 SG_ AerosolState_55 : 4|1@1+ (1,0) [0|1] ""  MBMU,PC
 SG_ AerosolFaultState_55 : 5|2@1+ (1,0) [0|3] ""  MBMU,PC
 SG_ DoorState_55 : 7|1@1+ (1,0) [0|1] ""  MBMU,PC
 SG_ ControlBoxFanState_55 : 8|1@1+ (1,0) [0|1] ""  MBMU,PC
 SG_ ControlBoxTempHighWarning_55 : 9|1@1+ (1,0) [0|1] ""  MBMU,PC
 SG_ PowerSWState_55 : 10|1@1+ (1,0) [0|1] ""  MBMU,PC
 SG_ FaultClearCommand_55 : 11|1@1+ (1,0) [0|1] ""  MBMU,PC

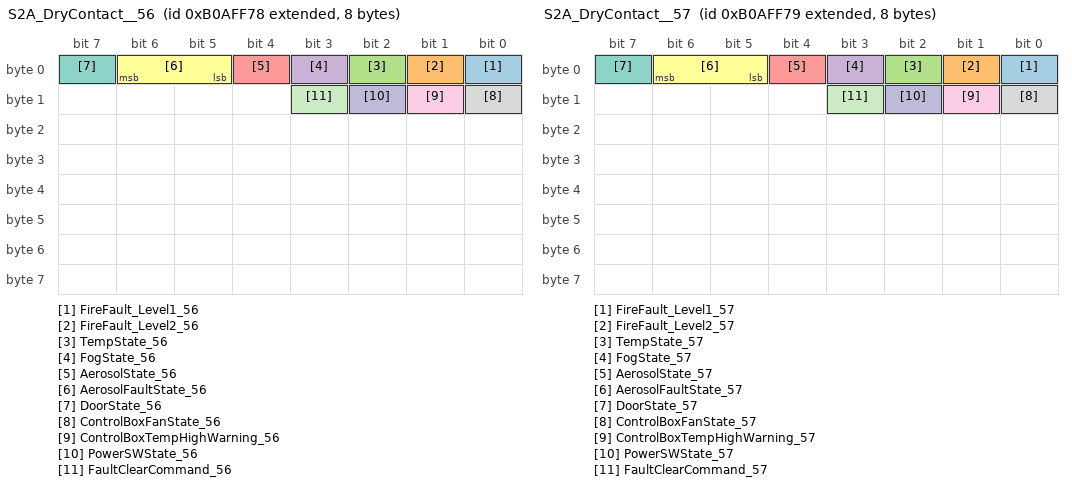
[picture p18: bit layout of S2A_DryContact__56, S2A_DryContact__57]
BO_ 2332753784 S2A_DryContact__56: 8 SBMU
 SG_ FireFault_Level1_56 : 0|1@1+ (1,0) [0|1] ""  MBMU,PC
 SG_ FireFault_Level2_56 : 1|1@1+ (1,0) [0|1] ""  MBMU,PC
 SG_ TempState_56 : 2|1@1+ (1,0) [0|1] ""  MBMU,PC
 SG_ FogState_56 : 3|1@1+ (1,0) [0|1] ""  MBMU,PC
 SG_ AerosolState_56 : 4|1@1+ (1,0) [0|1] ""  MBMU,PC
 SG_ AerosolFaultState_56 : 5|2@1+ (1,0) [0|3] ""  MBMU,PC
 SG_ DoorState_56 : 7|1@1+ (1,0) [0|1] ""  MBMU,PC
 SG_ ControlBoxFanState_56 : 8|1@1+ (1,0) [0|1] ""  MBMU,PC
 SG_ ControlBoxTempHighWarning_56 : 9|1@1+ (1,0) [0|1] ""  MBMU,PC
 SG_ PowerSWState_56 : 10|1@1+ (1,0) [0|1] ""  MBMU,PC
 SG_ FaultClearCommand_56 : 11|1@1+ (1,0) [0|1] ""  MBMU,PC

BO_ 2332753785 S2A_DryContact__57: 8 SBMU
 SG_ FireFault_Level1_57 : 0|1@1+ (1,0) [0|1] ""  MBMU,PC
 SG_ FireFault_Level2_57 : 1|1@1+ (1,0) [0|1] ""  MBMU,PC
 SG_ TempState_57 : 2|1@1+ (1,0) [0|1] ""  MBMU,PC
 SG_ FogState_57 : 3|1@1+ (1,0) [0|1] ""  MBMU,PC
 SG_ AerosolState_57 : 4|1@1+ (1,0) [0|1] ""  MBMU,PC
 SG_ AerosolFaultState_57 : 5|2@1+ (1,0) [0|3] ""  MBMU,PC
 SG_ DoorState_57 : 7|1@1+ (1,0) [0|1] ""  MBMU,PC
 SG_ ControlBoxFanState_57 : 8|1@1+ (1,0) [0|1] ""  MBMU,PC
 SG_ ControlBoxTempHighWarning_57 : 9|1@1+ (1,0) [0|1] ""  MBMU,PC
 SG_ PowerSWState_57 : 10|1@1+ (1,0) [0|1] ""  MBMU,PC
 SG_ FaultClearCommand_57 : 11|1@1+ (1,0) [0|1] ""  MBMU,PC

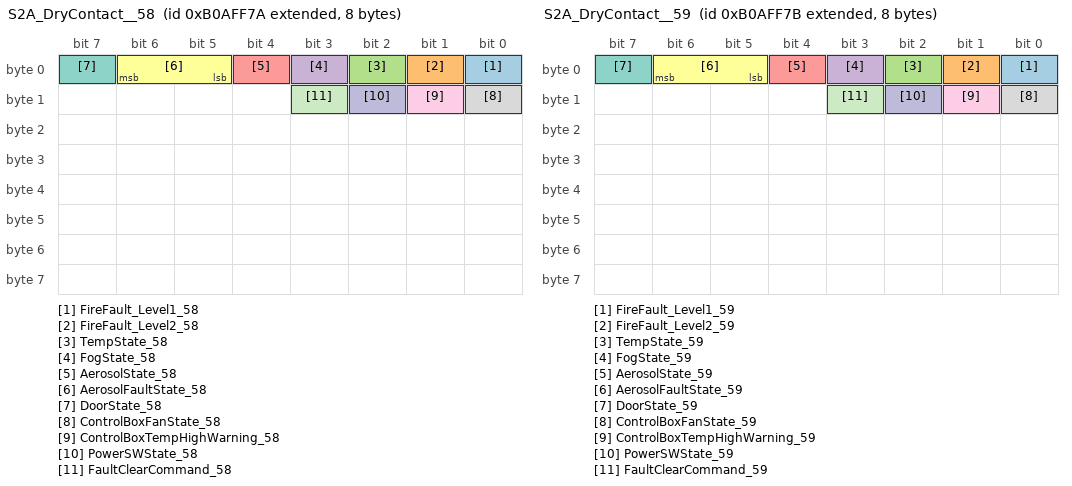
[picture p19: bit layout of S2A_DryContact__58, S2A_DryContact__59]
BO_ 2332753786 S2A_DryContact__58: 8 SBMU
 SG_ FireFault_Level1_58 : 0|1@1+ (1,0) [0|1] ""  MBMU,PC
 SG_ FireFault_Level2_58 : 1|1@1+ (1,0) [0|1] ""  MBMU,PC
 SG_ TempState_58 : 2|1@1+ (1,0) [0|1] ""  MBMU,PC
 SG_ FogState_58 : 3|1@1+ (1,0) [0|1] ""  MBMU,PC
 SG_ AerosolState_58 : 4|1@1+ (1,0) [0|1] ""  MBMU,PC
 SG_ AerosolFaultState_58 : 5|2@1+ (1,0) [0|3] ""  MBMU,PC
 SG_ DoorState_58 : 7|1@1+ (1,0) [0|1] ""  MBMU,PC
 SG_ ControlBoxFanState_58 : 8|1@1+ (1,0) [0|1] ""  MBMU,PC
 SG_ ControlBoxTempHighWarning_58 : 9|1@1+ (1,0) [0|1] ""  MBMU,PC
 SG_ PowerSWState_58 : 10|1@1+ (1,0) [0|1] ""  MBMU,PC
 SG_ FaultClearCommand_58 : 11|1@1+ (1,0) [0|1] ""  MBMU,PC

BO_ 2332753787 S2A_DryContact__59: 8 SBMU
 SG_ FireFault_Level1_59 : 0|1@1+ (1,0) [0|1] ""  MBMU,PC
 SG_ FireFault_Level2_59 : 1|1@1+ (1,0) [0|1] ""  MBMU,PC
 SG_ TempState_59 : 2|1@1+ (1,0) [0|1] ""  MBMU,PC
 SG_ FogState_59 : 3|1@1+ (1,0) [0|1] ""  MBMU,PC
 SG_ AerosolState_59 : 4|1@1+ (1,0) [0|1] ""  MBMU,PC
 SG_ AerosolFaultState_59 : 5|2@1+ (1,0) [0|3] ""  MBMU,PC
 SG_ DoorState_59 : 7|1@1+ (1,0) [0|1] ""  MBMU,PC
 SG_ ControlBoxFanState_59 : 8|1@1+ (1,0) [0|1] ""  MBMU,PC
 SG_ ControlBoxTempHighWarning_59 : 9|1@1+ (1,0) [0|1] ""  MBMU,PC
 SG_ PowerSWState_59 : 10|1@1+ (1,0) [0|1] ""  MBMU,PC
 SG_ FaultClearCommand_59 : 11|1@1+ (1,0) [0|1] ""  MBMU,PC

BO_ 2332753788 S2A_DryContact__60: 8 SBMU
 SG_ FireFault_Level1_60 : 0|1@1+ (1,0) [0|1] ""  MBMU,PC
 SG_ FireFault_Level2_60 : 1|1@1+ (1,0) [0|1] ""  MBMU,PC
 SG_ TempState_60 : 2|1@1+ (1,0) [0|1] ""  MBMU,PC
 SG_ FogState_60 : 3|1@1+ (1,0) [0|1] ""  MBMU,PC
 SG_ AerosolState_60 : 4|1@1+ (1,0) [0|1] ""  MBMU,PC
 SG_ AerosolFaultState_60 : 5|2@1+ (1,0) [0|3] ""  MBMU,PC
 SG_ DoorState_60 : 7|1@1+ (1,0) [0|1] ""  MBMU,PC
 SG_ ControlBoxFanState_60 : 8|1@1+ (1,0) [0|1] ""  MBMU,PC
 SG_ ControlBoxTempHighWarning_60 : 9|1@1+ (1,0) [0|1] ""  MBMU,PC
 SG_ PowerSWState_60 : 10|1@1+ (1,0) [0|1] ""  MBMU,PC
 SG_ FaultClearCommand_60 : 11|1@1+ (1,0) [0|1] ""  MBMU,PC

BO_ 2332753789 S2A_DryContact__61: 8 SBMU
 SG_ FireFault_Level1_61 : 0|1@1+ (1,0) [0|1] ""  MBMU,PC
 SG_ FireFault_Level2_61 : 1|1@1+ (1,0) [0|1] ""  MBMU,PC
 SG_ TempState_61 : 2|1@1+ (1,0) [0|1] ""  MBMU,PC
 SG_ FogState_61 : 3|1@1+ (1,0) [0|1] ""  MBMU,PC
 SG_ AerosolState_61 : 4|1@1+ (1,0) [0|1] ""  MBMU,PC
 SG_ AerosolFaultState_61 : 5|2@1+ (1,0) [0|3] ""  MBMU,PC
 SG_ DoorState_61 : 7|1@1+ (1,0) [0|1] ""  MBMU,PC
 SG_ ControlBoxFanState_61 : 8|1@1+ (1,0) [0|1] ""  MBMU,PC
 SG_ ControlBoxTempHighWarning_61 : 9|1@1+ (1,0) [0|1] ""  MBMU,PC
 SG_ PowerSWState_61 : 10|1@1+ (1,0) [0|1] ""  MBMU,PC
 SG_ FaultClearCommand_61 : 11|1@1+ (1,0) [0|1] ""  MBMU,PC

BO_ 2332753790 S2A_DryContact__62: 8 SBMU
 SG_ FireFault_Level1_62 : 0|1@1+ (1,0) [0|1] ""  MBMU,PC
 SG_ FireFault_Level2_62 : 1|1@1+ (1,0) [0|1] ""  MBMU,PC
 SG_ TempState_62 : 2|1@1+ (1,0) [0|1] ""  MBMU,PC
 SG_ FogState_62 : 3|1@1+ (1,0) [0|1] ""  MBMU,PC
 SG_ AerosolState_62 : 4|1@1+ (1,0) [0|1] ""  MBMU,PC
 SG_ AerosolFaultState_62 : 5|2@1+ (1,0) [0|3] ""  MBMU,PC
 SG_ DoorState_62 : 7|1@1+ (1,0) [0|1] ""  MBMU,PC
 SG_ ControlBoxFanState_62 : 8|1@1+ (1,0) [0|1] ""  MBMU,PC
 SG_ ControlBoxTempHighWarning_62 : 9|1@1+ (1,0) [0|1] ""  MBMU,PC
 SG_ PowerSWState_62 : 10|1@1+ (1,0) [0|1] ""  MBMU,PC
 SG_ FaultClearCommand_62 : 11|1@1+ (1,0) [0|1] ""  MBMU,PC

BO_ 2332753791 S2A_DryContact__63: 8 SBMU
 SG_ FireFault_Level1_63 : 0|1@1+ (1,0) [0|1] ""  MBMU,PC
 SG_ FireFault_Level2_63 : 1|1@1+ (1,0) [0|1] ""  MBMU,PC
 SG_ TempState_63 : 2|1@1+ (1,0) [0|1] ""  MBMU,PC
 SG_ FogState_63 : 3|1@1+ (1,0) [0|1] ""  MBMU,PC
 SG_ AerosolState_63 : 4|1@1+ (1,0) [0|1] ""  MBMU,PC
 SG_ AerosolFaultState_63 : 5|2@1+ (1,0) [0|3] ""  MBMU,PC
 SG_ DoorState_63 : 7|1@1+ (1,0) [0|1] ""  MBMU,PC
 SG_ ControlBoxFanState_63 : 8|1@1+ (1,0) [0|1] ""  MBMU,PC
 SG_ ControlBoxTempHighWarning_63 : 9|1@1+ (1,0) [0|1] ""  MBMU,PC
 SG_ PowerSWState_63 : 10|1@1+ (1,0) [0|1] ""  MBMU,PC
 SG_ FaultClearCommand_63 : 11|1@1+ (1,0) [0|1] ""  MBMU,PC

BO_ 2467491393 S2P_Index__01: 8 SBMU
 SG_ S2P_Index_ST_01 : 0|3@1+ (1,0) [0|7] ""  PC
 SG_ S2P_Index_Err_01 : 3|5@1+ (1,0) [0|31] ""  PC

BO_ 2467491394 S2P_Index__02: 8 SBMU
 SG_ S2P_Index_ST_02 : 0|3@1+ (1,0) [0|7] ""  PC
 SG_ S2P_Index_Err_02 : 3|5@1+ (1,0) [0|31] ""  PC

BO_ 2467491395 S2P_Index__03: 8 SBMU
 SG_ S2P_Index_ST_03 : 0|3@1+ (1,0) [0|7] ""  PC
 SG_ S2P_Index_Err_03 : 3|5@1+ (1,0) [0|31] ""  PC

BO_ 2467491396 S2P_Index__04: 8 SBMU
 SG_ S2P_Index_ST_04 : 0|3@1+ (1,0) [0|7] ""  PC
 SG_ S2P_Index_Err_04 : 3|5@1+ (1,0) [0|31] ""  PC

BO_ 2467491397 S2P_Index__05: 8 SBMU
 SG_ S2P_Index_ST_05 : 0|3@1+ (1,0) [0|7] ""  PC
 SG_ S2P_Index_Err_05 : 3|5@1+ (1,0) [0|31] ""  PC

BO_ 2467491398 S2P_Index__06: 8 SBMU
 SG_ S2P_Index_ST_06 : 0|3@1+ (1,0) [0|7] ""  PC
 SG_ S2P_Index_Err_06 : 3|5@1+ (1,0) [0|31] ""  PC

BO_ 2467491399 S2P_Index__07: 8 SBMU
 SG_ S2P_Index_ST_07 : 0|3@1+ (1,0) [0|7] ""  PC
 SG_ S2P_Index_Err_07 : 3|5@1+ (1,0) [0|31] ""  PC

BO_ 2467491400 S2P_Index__08: 8 SBMU
 SG_ S2P_Index_ST_08 : 0|3@1+ (1,0) [0|7] ""  PC
 SG_ S2P_Index_Err_08 : 3|5@1+ (1,0) [0|31] ""  PC

BO_ 2467491401 S2P_Index__09: 8 SBMU
 SG_ S2P_Index_ST_09 : 0|3@1+ (1,0) [0|7] ""  PC
 SG_ S2P_Index_Err_09 : 3|5@1+ (1,0) [0|31] ""  PC

BO_ 2467491402 S2P_Index__10: 8 SBMU
 SG_ S2P_Index_ST_10 : 0|3@1+ (1,0) [0|7] ""  PC
 SG_ S2P_Index_Err_10 : 3|5@1+ (1,0) [0|31] ""  PC

BO_ 2467491403 S2P_Index__11: 8 SBMU
 SG_ S2P_Index_ST_11 : 0|3@1+ (1,0) [0|7] ""  PC
 SG_ S2P_Index_Err_11 : 3|5@1+ (1,0) [0|31] ""  PC

BO_ 2467491404 S2P_Index__12: 8 SBMU
 SG_ S2P_Index_ST_12 : 0|3@1+ (1,0) [0|7] ""  PC
 SG_ S2P_Index_Err_12 : 3|5@1+ (1,0) [0|31] ""  PC

BO_ 2467491405 S2P_Index__13: 8 SBMU
 SG_ S2P_Index_ST_13 : 0|3@1+ (1,0) [0|7] ""  PC
 SG_ S2P_Index_Err_13 : 3|5@1+ (1,0) [0|31] ""  PC

BO_ 2467491406 S2P_Index__14: 8 SBMU
 SG_ S2P_Index_ST_14 : 0|3@1+ (1,0) [0|7] ""  PC
 SG_ S2P_Index_Err_14 : 3|5@1+ (1,0) [0|31] ""  PC

BO_ 2467491407 S2P_Index__15: 8 SBMU
 SG_ S2P_Index_ST_15 : 0|3@1+ (1,0) [0|7] ""  PC
 SG_ S2P_Index_Err_15 : 3|5@1+ (1,0) [0|31] ""  PC

BO_ 2467491408 S2P_Index__16: 8 SBMU
 SG_ S2P_Index_ST_16 : 0|3@1+ (1,0) [0|7] ""  PC
 SG_ S2P_Index_Err_16 : 3|5@1+ (1,0) [0|31] ""  PC

BO_ 2467491409 S2P_Index__17: 8 SBMU
 SG_ S2P_Index_ST_17 : 0|3@1+ (1,0) [0|7] ""  PC
 SG_ S2P_Index_Err_17 : 3|5@1+ (1,0) [0|31] ""  PC

BO_ 2467491410 S2P_Index__18: 8 SBMU
 SG_ S2P_Index_ST_18 : 0|3@1+ (1,0) [0|7] ""  PC
 SG_ S2P_Index_Err_18 : 3|5@1+ (1,0) [0|31] ""  PC

BO_ 2467491411 S2P_Index__19: 8 SBMU
 SG_ S2P_Index_ST_19 : 0|3@1+ (1,0) [0|7] ""  PC
 SG_ S2P_Index_Err_19 : 3|5@1+ (1,0) [0|31] ""  PC

BO_ 2467491412 S2P_Index__20: 8 SBMU
 SG_ S2P_Index_ST_20 : 0|3@1+ (1,0) [0|7] ""  PC
 SG_ S2P_Index_Err_20 : 3|5@1+ (1,0) [0|31] ""  PC

BO_ 2467491413 S2P_Index__21: 8 SBMU
 SG_ S2P_Index_ST_21 : 0|3@1+ (1,0) [0|7] ""  PC
 SG_ S2P_Index_Err_21 : 3|5@1+ (1,0) [0|31] ""  PC

BO_ 2467491414 S2P_Index__22: 8 SBMU
 SG_ S2P_Index_ST_22 : 0|3@1+ (1,0) [0|7] ""  PC
 SG_ S2P_Index_Err_22 : 3|5@1+ (1,0) [0|31] ""  PC

BO_ 2467491415 S2P_Index__23: 8 SBMU
 SG_ S2P_Index_ST_23 : 0|3@1+ (1,0) [0|7] ""  PC
 SG_ S2P_Index_Err_23 : 3|5@1+ (1,0) [0|31] ""  PC

BO_ 2467491416 S2P_Index__24: 8 SBMU
 SG_ S2P_Index_ST_24 : 0|3@1+ (1,0) [0|7] ""  PC
 SG_ S2P_Index_Err_24 : 3|5@1+ (1,0) [0|31] ""  PC

BO_ 2467491417 S2P_Index__25: 8 SBMU
 SG_ S2P_Index_ST_25 : 0|3@1+ (1,0) [0|7] ""  PC
 SG_ S2P_Index_Err_25 : 3|5@1+ (1,0) [0|31] ""  PC

BO_ 2467491418 S2P_Index__26: 8 SBMU
 SG_ S2P_Index_ST_26 : 0|3@1+ (1,0) [0|7] ""  PC
 SG_ S2P_Index_Err_26 : 3|5@1+ (1,0) [0|31] ""  PC

BO_ 2467491419 S2P_Index__27: 8 SBMU
 SG_ S2P_Index_ST_27 : 0|3@1+ (1,0) [0|7] ""  PC
 SG_ S2P_Index_Err_27 : 3|5@1+ (1,0) [0|31] ""  PC

BO_ 2467491420 S2P_Index__28: 8 SBMU
 SG_ S2P_Index_ST_28 : 0|3@1+ (1,0) [0|7] ""  PC
 SG_ S2P_Index_Err_28 : 3|5@1+ (1,0) [0|31] ""  PC

BO_ 2467491421 S2P_Index__29: 8 SBMU
 SG_ S2P_Index_ST_29 : 0|3@1+ (1,0) [0|7] ""  PC
 SG_ S2P_Index_Err_29 : 3|5@1+ (1,0) [0|31] ""  PC

BO_ 2467491422 S2P_Index__30: 8 SBMU
 SG_ S2P_Index_ST_30 : 0|3@1+ (1,0) [0|7] ""  PC
 SG_ S2P_Index_Err_30 : 3|5@1+ (1,0) [0|31] ""  PC

BO_ 2467491423 S2P_Index__31: 8 SBMU
 SG_ S2P_Index_ST_31 : 0|3@1+ (1,0) [0|7] ""  PC
 SG_ S2P_Index_Err_31 : 3|5@1+ (1,0) [0|31] ""  PC

BO_ 2467491424 S2P_Index__32: 8 SBMU
 SG_ S2P_Index_ST_32 : 0|3@1+ (1,0) [0|7] ""  PC
 SG_ S2P_Index_Err_32 : 3|5@1+ (1,0) [0|31] ""  PC

BO_ 2467491425 S2P_Index__33: 8 SBMU
 SG_ S2P_Index_ST_33 : 0|3@1+ (1,0) [0|7] ""  PC
 SG_ S2P_Index_Err_33 : 3|5@1+ (1,0) [0|31] ""  PC

BO_ 2467491426 S2P_Index__34: 8 SBMU
 SG_ S2P_Index_ST_34 : 0|3@1+ (1,0) [0|7] ""  PC
 SG_ S2P_Index_Err_34 : 3|5@1+ (1,0) [0|31] ""  PC

BO_ 2467491427 S2P_Index__35: 8 SBMU
 SG_ S2P_Index_ST_35 : 0|3@1+ (1,0) [0|7] ""  PC
 SG_ S2P_Index_Err_35 : 3|5@1+ (1,0) [0|31] ""  PC

BO_ 2467491428 S2P_Index__36: 8 SBMU
 SG_ S2P_Index_ST_36 : 0|3@1+ (1,0) [0|7] ""  PC
 SG_ S2P_Index_Err_36 : 3|5@1+ (1,0) [0|31] ""  PC

BO_ 2467491429 S2P_Index__37: 8 SBMU
 SG_ S2P_Index_ST_37 : 0|3@1+ (1,0) [0|7] ""  PC
 SG_ S2P_Index_Err_37 : 3|5@1+ (1,0) [0|31] ""  PC

BO_ 2467491430 S2P_Index__38: 8 SBMU
 SG_ S2P_Index_ST_38 : 0|3@1+ (1,0) [0|7] ""  PC
 SG_ S2P_Index_Err_38 : 3|5@1+ (1,0) [0|31] ""  PC

BO_ 2467491431 S2P_Index__39: 8 SBMU
 SG_ S2P_Index_ST_39 : 0|3@1+ (1,0) [0|7] ""  PC
 SG_ S2P_Index_Err_39 : 3|5@1+ (1,0) [0|31] ""  PC

BO_ 2467491432 S2P_Index__40: 8 SBMU
 SG_ S2P_Index_ST_40 : 0|3@1+ (1,0) [0|7] ""  PC
 SG_ S2P_Index_Err_40 : 3|5@1+ (1,0) [0|31] ""  PC

BO_ 2467491433 S2P_Index__41: 8 SBMU
 SG_ S2P_Index_ST_41 : 0|3@1+ (1,0) [0|7] ""  PC
 SG_ S2P_Index_Err_41 : 3|5@1+ (1,0) [0|31] ""  PC

BO_ 2467491434 S2P_Index__42: 8 SBMU
 SG_ S2P_Index_ST_42 : 0|3@1+ (1,0) [0|7] ""  PC
 SG_ S2P_Index_Err_42 : 3|5@1+ (1,0) [0|31] ""  PC

BO_ 2467491435 S2P_Index__43: 8 SBMU
 SG_ S2P_Index_ST_43 : 0|3@1+ (1,0) [0|7] ""  PC
 SG_ S2P_Index_Err_43 : 3|5@1+ (1,0) [0|31] ""  PC

BO_ 2467491436 S2P_Index__44: 8 SBMU
 SG_ S2P_Index_ST_44 : 0|3@1+ (1,0) [0|7] ""  PC
 SG_ S2P_Index_Err_44 : 3|5@1+ (1,0) [0|31] ""  PC

BO_ 2467491437 S2P_Index__45: 8 SBMU
 SG_ S2P_Index_ST_45 : 0|3@1+ (1,0) [0|7] ""  PC
 SG_ S2P_Index_Err_45 : 3|5@1+ (1,0) [0|31] ""  PC

BO_ 2467491438 S2P_Index__46: 8 SBMU
 SG_ S2P_Index_ST_46 : 0|3@1+ (1,0) [0|7] ""  PC
 SG_ S2P_Index_Err_46 : 3|5@1+ (1,0) [0|31] ""  PC

BO_ 2467491439 S2P_Index__47: 8 SBMU
 SG_ S2P_Index_ST_47 : 0|3@1+ (1,0) [0|7] ""  PC
 SG_ S2P_Index_Err_47 : 3|5@1+ (1,0) [0|31] ""  PC

BO_ 2467491440 S2P_Index__48: 8 SBMU
 SG_ S2P_Index_ST_48 : 0|3@1+ (1,0) [0|7] ""  PC
 SG_ S2P_Index_Err_48 : 3|5@1+ (1,0) [0|31] ""  PC

BO_ 2467491441 S2P_Index__49: 8 SBMU
 SG_ S2P_Index_ST_49 : 0|3@1+ (1,0) [0|7] ""  PC
 SG_ S2P_Index_Err_49 : 3|5@1+ (1,0) [0|31] ""  PC

BO_ 2467491442 S2P_Index__50: 8 SBMU
 SG_ S2P_Index_ST_50 : 0|3@1+ (1,0) [0|7] ""  PC
 SG_ S2P_Index_Err_50 : 3|5@1+ (1,0) [0|31] ""  PC

BO_ 2467491443 S2P_Index__51: 8 SBMU
 SG_ S2P_Index_ST_51 : 0|3@1+ (1,0) [0|7] ""  PC
 SG_ S2P_Index_Err_51 : 3|5@1+ (1,0) [0|31] ""  PC

BO_ 2467491444 S2P_Index__52: 8 SBMU
 SG_ S2P_Index_ST_52 : 0|3@1+ (1,0) [0|7] ""  PC
 SG_ S2P_Index_Err_52 : 3|5@1+ (1,0) [0|31] ""  PC

BO_ 2467491445 S2P_Index__53: 8 SBMU
 SG_ S2P_Index_ST_53 : 0|3@1+ (1,0) [0|7] ""  PC
 SG_ S2P_Index_Err_53 : 3|5@1+ (1,0) [0|31] ""  PC

BO_ 2467491446 S2P_Index__54: 8 SBMU
 SG_ S2P_Index_ST_54 : 0|3@1+ (1,0) [0|7] ""  PC
 SG_ S2P_Index_Err_54 : 3|5@1+ (1,0) [0|31] ""  PC

BO_ 2467491447 S2P_Index__55: 8 SBMU
 SG_ S2P_Index_ST_55 : 0|3@1+ (1,0) [0|7] ""  PC
 SG_ S2P_Index_Err_55 : 3|5@1+ (1,0) [0|31] ""  PC

BO_ 2467491448 S2P_Index__56: 8 SBMU
 SG_ S2P_Index_ST_56 : 0|3@1+ (1,0) [0|7] ""  PC
 SG_ S2P_Index_Err_56 : 3|5@1+ (1,0) [0|31] ""  PC

BO_ 2467491449 S2P_Index__57: 8 SBMU
 SG_ S2P_Index_ST_57 : 0|3@1+ (1,0) [0|7] ""  PC
 SG_ S2P_Index_Err_57 : 3|5@1+ (1,0) [0|31] ""  PC

BO_ 2467491450 S2P_Index__58: 8 SBMU
 SG_ S2P_Index_ST_58 : 0|3@1+ (1,0) [0|7] ""  PC
 SG_ S2P_Index_Err_58 : 3|5@1+ (1,0) [0|31] ""  PC

BO_ 2467491451 S2P_Index__59: 8 SBMU
 SG_ S2P_Index_ST_59 : 0|3@1+ (1,0) [0|7] ""  PC
 SG_ S2P_Index_Err_59 : 3|5@1+ (1,0) [0|31] ""  PC

BO_ 2467491452 S2P_Index__60: 8 SBMU
 SG_ S2P_Index_ST_60 : 0|3@1+ (1,0) [0|7] ""  PC
 SG_ S2P_Index_Err_60 : 3|5@1+ (1,0) [0|31] ""  PC

BO_ 2467491453 S2P_Index__61: 8 SBMU
 SG_ S2P_Index_ST_61 : 0|3@1+ (1,0) [0|7] ""  PC
 SG_ S2P_Index_Err_61 : 3|5@1+ (1,0) [0|31] ""  PC

BO_ 2467491454 S2P_Index__62: 8 SBMU
 SG_ S2P_Index_ST_62 : 0|3@1+ (1,0) [0|7] ""  PC
 SG_ S2P_Index_Err_62 : 3|5@1+ (1,0) [0|31] ""  PC

BO_ 2467491455 S2P_Index__63: 8 SBMU
 SG_ S2P_Index_ST_63 : 0|3@1+ (1,0) [0|7] ""  PC
 SG_ S2P_Index_Err_63 : 3|5@1+ (1,0) [0|31] ""  PC

BO_ 2400316993 S2P_Detail_Ucell1__01: 8 SBMU
 SG_ CSC_U_No_01 : 0|8@1+ (1,0) [0|255] ""  PC
 SG_ CSC_Ucell_Frame_Index_01 M : 8|8@1+ (1,0) [0|255] ""  PC
 SG_ CSC_Ucell_01_01 m0 : 16|16@1+ (1,0) [0|65535] "mV"  PC
 SG_ CSC_Ucell_02_01 m0 : 32|16@1+ (1,0) [0|65535] "mV"  PC
 SG_ CSC_Ucell_03_01 m0 : 48|16@1+ (1,0) [0|65535] "mV"  PC
 SG_ CSC_Ucell_04_01 m1 : 16|16@1+ (1,0) [0|65535] "mV"  PC
 SG_ CSC_Ucell_05_01 m1 : 32|16@1+ (1,0) [0|65535] "mV"  PC
 SG_ CSC_Ucell_06_01 m1 : 48|16@1+ (1,0) [0|65535] "mV"  PC
 SG_ CSC_Ucell_07_01 m2 : 16|16@1+ (1,0) [0|65535] "mV"  PC
 SG_ CSC_Ucell_08_01 m2 : 32|16@1+ (1,0) [0|65535] "mV"  PC
 SG_ CSC_Ucell_09_01 m2 : 48|16@1+ (1,0) [0|65535] "mV"  PC
 SG_ CSC_Ucell_10_01 m3 : 16|16@1+ (1,0) [0|65535] "mV"  PC
 SG_ CSC_Ucell_11_01 m3 : 32|16@1+ (1,0) [0|65535] "mV"  PC
 SG_ CSC_Ucell_12_01 m3 : 48|16@1+ (1,0) [0|65535] "mV"  PC
 SG_ CSC_Ucell_13_01 m4 : 16|16@1+ (1,0) [0|65535] "mV"  PC
 SG_ CSC_Ucell_14_01 m4 : 32|16@1+ (1,0) [0|65535] "mV"  PC
 SG_ CSC_Ucell_15_01 m4 : 48|16@1+ (1,0) [0|65535] "mV"  PC
 SG_ CSC_Ucell_16_01 m5 : 16|16@1+ (1,0) [0|65535] "mV"  PC
 SG_ CSC_Ucell_17_01 m5 : 32|16@1+ (1,0) [0|65535] "mV"  PC
 SG_ CSC_Ucell_18_01 m5 : 48|16@1+ (1,0) [0|65535] "mV"  PC
 SG_ CSC_Ucell_19_01 m6 : 16|16@1+ (1,0) [0|65535] "mV"  PC
 SG_ CSC_Ucell_20_01 m6 : 32|16@1+ (1,0) [0|65535] "mV"  PC
 SG_ CSC_Ucell_21_01 m6 : 48|16@1+ (1,0) [0|65535] "mV"  PC
 SG_ CSC_Ucell_22_01 m7 : 16|16@1+ (1,0) [0|65535] "mV"  PC
 SG_ CSC_Ucell_23_01 m7 : 32|16@1+ (1,0) [0|65535] "mV"  PC
 SG_ CSC_Ucell_24_01 m7 : 48|16@1+ (1,0) [0|65535] "mV"  PC
 SG_ CSC_Ucell_25_01 m8 : 16|16@1+ (1,0) [0|65535] "mV"  PC
 SG_ CSC_Ucell_26_01 m8 : 32|16@1+ (1,0) [0|65535] "mV"  PC
 SG_ CSC_Ucell_27_01 m8 : 48|16@1+ (1,0) [0|65535] "mV"  PC
 SG_ CSC_Ucell_28_01 m9 : 16|16@1+ (1,0) [0|65535] "mV"  PC
 SG_ CSC_Ucell_29_01 m9 : 32|16@1+ (1,0) [0|65535] "mV"  PC
 SG_ CSC_Ucell_30_01 m9 : 48|16@1+ (1,0) [0|65535] "mV"  PC
 SG_ CSC_Ucell_31_01 m10 : 16|16@1+ (1,0) [0|65535] "mV"  PC
 SG_ CSC_Ucell_32_01 m10 : 32|16@1+ (1,0) [0|65535] "mV"  PC
 SG_ CSC_Ucell_33_01 m10 : 48|16@1+ (1,0) [0|65535] "mV"  PC
 SG_ CSC_Ucell_34_01 m11 : 16|16@1+ (1,0) [0|65535] "mV"  PC
 SG_ CSC_Ucell_35_01 m11 : 32|16@1+ (1,0) [0|65535] "mV"  PC
 SG_ CSC_Ucell_36_01 m11 : 48|16@1+ (1,0) [0|65535] "mV"  PC
 SG_ CSC_Ucell_37_01 m12 : 16|16@1+ (1,0) [0|65535] "mV"  PC
 SG_ CSC_Ucell_38_01 m12 : 32|16@1+ (1,0) [0|65535] "mV"  PC
 SG_ CSC_Ucell_39_01 m12 : 48|16@1+ (1,0) [0|65535] "mV"  PC
 SG_ CSC_Ucell_40_01 m13 : 16|16@1+ (1,0) [0|65535] "mV"  PC
 SG_ CSC_Ucell_41_01 m13 : 32|16@1+ (1,0) [0|65535] "mV"  PC
 SG_ CSC_Ucell_42_01 m13 : 48|16@1+ (1,0) [0|65535] "mV"  PC
 SG_ CSC_Ucell_43_01 m14 : 16|16@1+ (1,0) [0|65535] "mV"  PC
 SG_ CSC_Ucell_44_01 m14 : 32|16@1+ (1,0) [0|65535] "mV"  PC
 SG_ CSC_Ucell_45_01 m14 : 48|16@1+ (1,0) [0|65535] "mV"  PC
 SG_ CSC_Ucell_46_01 m15 : 16|16@1+ (1,0) [0|65535] "mV"  PC
 SG_ CSC_Ucell_47_01 m15 : 32|16@1+ (1,0) [0|65535] "mV"  PC
 SG_ CSC_Ucell_48_01 m15 : 48|16@1+ (1,0) [0|65535] "mV"  PC
 SG_ CSC_Ucell_49_01 m16 : 16|16@1+ (1,0) [0|65535] "mV"  PC
 SG_ CSC_Ucell_50_01 m16 : 32|16@1+ (1,0) [0|65535] "mV"  PC
 SG_ CSC_Ucell_51_01 m16 : 48|16@1+ (1,0) [0|65535] "mV"  PC
 SG_ CSC_Ucell_52_01 m17 : 16|16@1+ (1,0) [0|65535] "mV"  PC
 SG_ CSC_Ucell_53_01 m17 : 32|16@1+ (1,0) [0|65535] "mV"  PC
 SG_ CSC_Ucell_54_01 m17 : 48|16@1+ (1,0) [0|65535] "mV"  PC
 SG_ CSC_Ucell_55_01 m18 : 16|16@1+ (1,0) [0|65535] "mV"  PC
 SG_ CSC_Ucell_56_01 m18 : 32|16@1+ (1,0) [0|65535] "mV"  PC
 SG_ CSC_Ucell_57_01 m18 : 48|16@1+ (1,0) [0|65535] ""  PC

BO_ 2400316994 S2P_Detail_Ucell1__02: 8 SBMU
 SG_ CSC_U_No_02 : 0|8@1+ (1,0) [0|255] ""  PC
 SG_ CSC_Ucell_Frame_Index_02 M : 8|8@1+ (1,0) [0|255] ""  PC
 SG_ CSC_Ucell_01_02 m0 : 16|16@1+ (1,0) [0|65535] "mV"  PC
 SG_ CSC_Ucell_02_02 m0 : 32|16@1+ (1,0) [0|65535] "mV"  PC
 SG_ CSC_Ucell_03_02 m0 : 48|16@1+ (1,0) [0|65535] "mV"  PC
 SG_ CSC_Ucell_04_02 m1 : 16|16@1+ (1,0) [0|65535] "mV"  PC
 SG_ CSC_Ucell_05_02 m1 : 32|16@1+ (1,0) [0|65535] "mV"  PC
 SG_ CSC_Ucell_06_02 m1 : 48|16@1+ (1,0) [0|65535] "mV"  PC
 SG_ CSC_Ucell_07_02 m2 : 16|16@1+ (1,0) [0|65535] "mV"  PC
 SG_ CSC_Ucell_08_02 m2 : 32|16@1+ (1,0) [0|65535] "mV"  PC
 SG_ CSC_Ucell_09_02 m2 : 48|16@1+ (1,0) [0|65535] "mV"  PC
 SG_ CSC_Ucell_10_02 m3 : 16|16@1+ (1,0) [0|65535] "mV"  PC
 SG_ CSC_Ucell_11_02 m3 : 32|16@1+ (1,0) [0|65535] "mV"  PC
 SG_ CSC_Ucell_12_02 m3 : 48|16@1+ (1,0) [0|65535] "mV"  PC
 SG_ CSC_Ucell_13_02 m4 : 16|16@1+ (1,0) [0|65535] "mV"  PC
 SG_ CSC_Ucell_14_02 m4 : 32|16@1+ (1,0) [0|65535] "mV"  PC
 SG_ CSC_Ucell_15_02 m4 : 48|16@1+ (1,0) [0|65535] "mV"  PC
 SG_ CSC_Ucell_16_02 m5 : 16|16@1+ (1,0) [0|65535] "mV"  PC
 SG_ CSC_Ucell_17_02 m5 : 32|16@1+ (1,0) [0|65535] "mV"  PC
 SG_ CSC_Ucell_18_02 m5 : 48|16@1+ (1,0) [0|65535] "mV"  PC
 SG_ CSC_Ucell_19_02 m6 : 16|16@1+ (1,0) [0|65535] "mV"  PC
 SG_ CSC_Ucell_20_02 m6 : 32|16@1+ (1,0) [0|65535] "mV"  PC
 SG_ CSC_Ucell_21_02 m6 : 48|16@1+ (1,0) [0|65535] "mV"  PC
 SG_ CSC_Ucell_22_02 m7 : 16|16@1+ (1,0) [0|65535] "mV"  PC
 SG_ CSC_Ucell_23_02 m7 : 32|16@1+ (1,0) [0|65535] "mV"  PC
 SG_ CSC_Ucell_24_02 m7 : 48|16@1+ (1,0) [0|65535] "mV"  PC
 SG_ CSC_Ucell_25_02 m8 : 16|16@1+ (1,0) [0|65535] "mV"  PC
 SG_ CSC_Ucell_26_02 m8 : 32|16@1+ (1,0) [0|65535] "mV"  PC
 SG_ CSC_Ucell_27_02 m8 : 48|16@1+ (1,0) [0|65535] "mV"  PC
 SG_ CSC_Ucell_28_02 m9 : 16|16@1+ (1,0) [0|65535] "mV"  PC
 SG_ CSC_Ucell_29_02 m9 : 32|16@1+ (1,0) [0|65535] "mV"  PC
 SG_ CSC_Ucell_30_02 m9 : 48|16@1+ (1,0) [0|65535] "mV"  PC
 SG_ CSC_Ucell_31_02 m10 : 16|16@1+ (1,0) [0|65535] "mV"  PC
 SG_ CSC_Ucell_32_02 m10 : 32|16@1+ (1,0) [0|65535] "mV"  PC
 SG_ CSC_Ucell_33_02 m10 : 48|16@1+ (1,0) [0|65535] "mV"  PC
 SG_ CSC_Ucell_34_02 m11 : 16|16@1+ (1,0) [0|65535] "mV"  PC
 SG_ CSC_Ucell_35_02 m11 : 32|16@1+ (1,0) [0|65535] "mV"  PC
 SG_ CSC_Ucell_36_02 m11 : 48|16@1+ (1,0) [0|65535] "mV"  PC
 SG_ CSC_Ucell_37_02 m12 : 16|16@1+ (1,0) [0|65535] "mV"  PC
 SG_ CSC_Ucell_38_02 m12 : 32|16@1+ (1,0) [0|65535] "mV"  PC
 SG_ CSC_Ucell_39_02 m12 : 48|16@1+ (1,0) [0|65535] "mV"  PC
 SG_ CSC_Ucell_40_02 m13 : 16|16@1+ (1,0) [0|65535] "mV"  PC
 SG_ CSC_Ucell_41_02 m13 : 32|16@1+ (1,0) [0|65535] "mV"  PC
 SG_ CSC_Ucell_42_02 m13 : 48|16@1+ (1,0) [0|65535] "mV"  PC
 SG_ CSC_Ucell_43_02 m14 : 16|16@1+ (1,0) [0|65535] "mV"  PC
 SG_ CSC_Ucell_44_02 m14 : 32|16@1+ (1,0) [0|65535] "mV"  PC
 SG_ CSC_Ucell_45_02 m14 : 48|16@1+ (1,0) [0|65535] "mV"  PC
 SG_ CSC_Ucell_46_02 m15 : 16|16@1+ (1,0) [0|65535] "mV"  PC
 SG_ CSC_Ucell_47_02 m15 : 32|16@1+ (1,0) [0|65535] "mV"  PC
 SG_ CSC_Ucell_48_02 m15 : 48|16@1+ (1,0) [0|65535] "mV"  PC
 SG_ CSC_Ucell_49_02 m16 : 16|16@1+ (1,0) [0|65535] "mV"  PC
 SG_ CSC_Ucell_50_02 m16 : 32|16@1+ (1,0) [0|65535] "mV"  PC
 SG_ CSC_Ucell_51_02 m16 : 48|16@1+ (1,0) [0|65535] "mV"  PC
 SG_ CSC_Ucell_52_02 m17 : 16|16@1+ (1,0) [0|65535] "mV"  PC
 SG_ CSC_Ucell_53_02 m17 : 32|16@1+ (1,0) [0|65535] "mV"  PC
 SG_ CSC_Ucell_54_02 m17 : 48|16@1+ (1,0) [0|65535] "mV"  PC
 SG_ CSC_Ucell_55_02 m18 : 16|16@1+ (1,0) [0|65535] "mV"  PC
 SG_ CSC_Ucell_56_02 m18 : 32|16@1+ (1,0) [0|65535] "mV"  PC
 SG_ CSC_Ucell_57_02 m18 : 48|16@1+ (1,0) [0|65535] ""  PC

BO_ 2400316995 S2P_Detail_Ucell1__03: 8 SBMU
 SG_ CSC_U_No_03 : 0|8@1+ (1,0) [0|255] ""  PC
 SG_ CSC_Ucell_Frame_Index_03 M : 8|8@1+ (1,0) [0|255] ""  PC
 SG_ CSC_Ucell_01_03 m0 : 16|16@1+ (1,0) [0|65535] "mV"  PC
 SG_ CSC_Ucell_02_03 m0 : 32|16@1+ (1,0) [0|65535] "mV"  PC
 SG_ CSC_Ucell_03_03 m0 : 48|16@1+ (1,0) [0|65535] "mV"  PC
 SG_ CSC_Ucell_04_03 m1 : 16|16@1+ (1,0) [0|65535] "mV"  PC
 SG_ CSC_Ucell_05_03 m1 : 32|16@1+ (1,0) [0|65535] "mV"  PC
 SG_ CSC_Ucell_06_03 m1 : 48|16@1+ (1,0) [0|65535] "mV"  PC
 SG_ CSC_Ucell_07_03 m2 : 16|16@1+ (1,0) [0|65535] "mV"  PC
 SG_ CSC_Ucell_08_03 m2 : 32|16@1+ (1,0) [0|65535] "mV"  PC
 SG_ CSC_Ucell_09_03 m2 : 48|16@1+ (1,0) [0|65535] "mV"  PC
 SG_ CSC_Ucell_10_03 m3 : 16|16@1+ (1,0) [0|65535] "mV"  PC
 SG_ CSC_Ucell_11_03 m3 : 32|16@1+ (1,0) [0|65535] "mV"  PC
 SG_ CSC_Ucell_12_03 m3 : 48|16@1+ (1,0) [0|65535] "mV"  PC
 SG_ CSC_Ucell_13_03 m4 : 16|16@1+ (1,0) [0|65535] "mV"  PC
 SG_ CSC_Ucell_14_03 m4 : 32|16@1+ (1,0) [0|65535] "mV"  PC
 SG_ CSC_Ucell_15_03 m4 : 48|16@1+ (1,0) [0|65535] "mV"  PC
 SG_ CSC_Ucell_16_03 m5 : 16|16@1+ (1,0) [0|65535] "mV"  PC
 SG_ CSC_Ucell_17_03 m5 : 32|16@1+ (1,0) [0|65535] "mV"  PC
 SG_ CSC_Ucell_18_03 m5 : 48|16@1+ (1,0) [0|65535] "mV"  PC
 SG_ CSC_Ucell_19_03 m6 : 16|16@1+ (1,0) [0|65535] "mV"  PC
 SG_ CSC_Ucell_20_03 m6 : 32|16@1+ (1,0) [0|65535] "mV"  PC
 SG_ CSC_Ucell_21_03 m6 : 48|16@1+ (1,0) [0|65535] "mV"  PC
 SG_ CSC_Ucell_22_03 m7 : 16|16@1+ (1,0) [0|65535] "mV"  PC
 SG_ CSC_Ucell_23_03 m7 : 32|16@1+ (1,0) [0|65535] "mV"  PC
 SG_ CSC_Ucell_24_03 m7 : 48|16@1+ (1,0) [0|65535] "mV"  PC
 SG_ CSC_Ucell_25_03 m8 : 16|16@1+ (1,0) [0|65535] "mV"  PC
 SG_ CSC_Ucell_26_03 m8 : 32|16@1+ (1,0) [0|65535] "mV"  PC
 SG_ CSC_Ucell_27_03 m8 : 48|16@1+ (1,0) [0|65535] "mV"  PC
 SG_ CSC_Ucell_28_03 m9 : 16|16@1+ (1,0) [0|65535] "mV"  PC
 SG_ CSC_Ucell_29_03 m9 : 32|16@1+ (1,0) [0|65535] "mV"  PC
 SG_ CSC_Ucell_30_03 m9 : 48|16@1+ (1,0) [0|65535] "mV"  PC
 SG_ CSC_Ucell_31_03 m10 : 16|16@1+ (1,0) [0|65535] "mV"  PC
 SG_ CSC_Ucell_32_03 m10 : 32|16@1+ (1,0) [0|65535] "mV"  PC
 SG_ CSC_Ucell_33_03 m10 : 48|16@1+ (1,0) [0|65535] "mV"  PC
 SG_ CSC_Ucell_34_03 m11 : 16|16@1+ (1,0) [0|65535] "mV"  PC
 SG_ CSC_Ucell_35_03 m11 : 32|16@1+ (1,0) [0|65535] "mV"  PC
 SG_ CSC_Ucell_36_03 m11 : 48|16@1+ (1,0) [0|65535] "mV"  PC
 SG_ CSC_Ucell_37_03 m12 : 16|16@1+ (1,0) [0|65535] "mV"  PC
 SG_ CSC_Ucell_38_03 m12 : 32|16@1+ (1,0) [0|65535] "mV"  PC
 SG_ CSC_Ucell_39_03 m12 : 48|16@1+ (1,0) [0|65535] "mV"  PC
 SG_ CSC_Ucell_40_03 m13 : 16|16@1+ (1,0) [0|65535] "mV"  PC
 SG_ CSC_Ucell_41_03 m13 : 32|16@1+ (1,0) [0|65535] "mV"  PC
 SG_ CSC_Ucell_42_03 m13 : 48|16@1+ (1,0) [0|65535] "mV"  PC
 SG_ CSC_Ucell_43_03 m14 : 16|16@1+ (1,0) [0|65535] "mV"  PC
 SG_ CSC_Ucell_44_03 m14 : 32|16@1+ (1,0) [0|65535] "mV"  PC
 SG_ CSC_Ucell_45_03 m14 : 48|16@1+ (1,0) [0|65535] "mV"  PC
 SG_ CSC_Ucell_46_03 m15 : 16|16@1+ (1,0) [0|65535] "mV"  PC
 SG_ CSC_Ucell_47_03 m15 : 32|16@1+ (1,0) [0|65535] "mV"  PC
 SG_ CSC_Ucell_48_03 m15 : 48|16@1+ (1,0) [0|65535] "mV"  PC
 SG_ CSC_Ucell_49_03 m16 : 16|16@1+ (1,0) [0|65535] "mV"  PC
 SG_ CSC_Ucell_50_03 m16 : 32|16@1+ (1,0) [0|65535] "mV"  PC
 SG_ CSC_Ucell_51_03 m16 : 48|16@1+ (1,0) [0|65535] "mV"  PC
 SG_ CSC_Ucell_52_03 m17 : 16|16@1+ (1,0) [0|65535] "mV"  PC
 SG_ CSC_Ucell_53_03 m17 : 32|16@1+ (1,0) [0|65535] "mV"  PC
 SG_ CSC_Ucell_54_03 m17 : 48|16@1+ (1,0) [0|65535] "mV"  PC
 SG_ CSC_Ucell_55_03 m18 : 16|16@1+ (1,0) [0|65535] "mV"  PC
 SG_ CSC_Ucell_56_03 m18 : 32|16@1+ (1,0) [0|65535] "mV"  PC
 SG_ CSC_Ucell_57_03 m18 : 48|16@1+ (1,0) [0|65535] ""  PC

BO_ 2400316996 S2P_Detail_Ucell1__04: 8 SBMU
 SG_ CSC_U_No_04 : 0|8@1+ (1,0) [0|255] ""  PC
 SG_ CSC_Ucell_Frame_Index_04 M : 8|8@1+ (1,0) [0|255] ""  PC
 SG_ CSC_Ucell_01_04 m0 : 16|16@1+ (1,0) [0|65535] "mV"  PC
 SG_ CSC_Ucell_02_04 m0 : 32|16@1+ (1,0) [0|65535] "mV"  PC
 SG_ CSC_Ucell_03_04 m0 : 48|16@1+ (1,0) [0|65535] "mV"  PC
 SG_ CSC_Ucell_04_04 m1 : 16|16@1+ (1,0) [0|65535] "mV"  PC
 SG_ CSC_Ucell_05_04 m1 : 32|16@1+ (1,0) [0|65535] "mV"  PC
 SG_ CSC_Ucell_06_04 m1 : 48|16@1+ (1,0) [0|65535] "mV"  PC
 SG_ CSC_Ucell_07_04 m2 : 16|16@1+ (1,0) [0|65535] "mV"  PC
 SG_ CSC_Ucell_08_04 m2 : 32|16@1+ (1,0) [0|65535] "mV"  PC
 SG_ CSC_Ucell_09_04 m2 : 48|16@1+ (1,0) [0|65535] "mV"  PC
 SG_ CSC_Ucell_10_04 m3 : 16|16@1+ (1,0) [0|65535] "mV"  PC
 SG_ CSC_Ucell_11_04 m3 : 32|16@1+ (1,0) [0|65535] "mV"  PC
 SG_ CSC_Ucell_12_04 m3 : 48|16@1+ (1,0) [0|65535] "mV"  PC
 SG_ CSC_Ucell_13_04 m4 : 16|16@1+ (1,0) [0|65535] "mV"  PC
 SG_ CSC_Ucell_14_04 m4 : 32|16@1+ (1,0) [0|65535] "mV"  PC
 SG_ CSC_Ucell_15_04 m4 : 48|16@1+ (1,0) [0|65535] "mV"  PC
 SG_ CSC_Ucell_16_04 m5 : 16|16@1+ (1,0) [0|65535] "mV"  PC
 SG_ CSC_Ucell_17_04 m5 : 32|16@1+ (1,0) [0|65535] "mV"  PC
 SG_ CSC_Ucell_18_04 m5 : 48|16@1+ (1,0) [0|65535] "mV"  PC
 SG_ CSC_Ucell_19_04 m6 : 16|16@1+ (1,0) [0|65535] "mV"  PC
 SG_ CSC_Ucell_20_04 m6 : 32|16@1+ (1,0) [0|65535] "mV"  PC
 SG_ CSC_Ucell_21_04 m6 : 48|16@1+ (1,0) [0|65535] "mV"  PC
 SG_ CSC_Ucell_22_04 m7 : 16|16@1+ (1,0) [0|65535] "mV"  PC
 SG_ CSC_Ucell_23_04 m7 : 32|16@1+ (1,0) [0|65535] "mV"  PC
 SG_ CSC_Ucell_24_04 m7 : 48|16@1+ (1,0) [0|65535] "mV"  PC
 SG_ CSC_Ucell_25_04 m8 : 16|16@1+ (1,0) [0|65535] "mV"  PC
 SG_ CSC_Ucell_26_04 m8 : 32|16@1+ (1,0) [0|65535] "mV"  PC
 SG_ CSC_Ucell_27_04 m8 : 48|16@1+ (1,0) [0|65535] "mV"  PC
 SG_ CSC_Ucell_28_04 m9 : 16|16@1+ (1,0) [0|65535] "mV"  PC
 SG_ CSC_Ucell_29_04 m9 : 32|16@1+ (1,0) [0|65535] "mV"  PC
 SG_ CSC_Ucell_30_04 m9 : 48|16@1+ (1,0) [0|65535] "mV"  PC
 SG_ CSC_Ucell_31_04 m10 : 16|16@1+ (1,0) [0|65535] "mV"  PC
 SG_ CSC_Ucell_32_04 m10 : 32|16@1+ (1,0) [0|65535] "mV"  PC
 SG_ CSC_Ucell_33_04 m10 : 48|16@1+ (1,0) [0|65535] "mV"  PC
 SG_ CSC_Ucell_34_04 m11 : 16|16@1+ (1,0) [0|65535] "mV"  PC
 SG_ CSC_Ucell_35_04 m11 : 32|16@1+ (1,0) [0|65535] "mV"  PC
 SG_ CSC_Ucell_36_04 m11 : 48|16@1+ (1,0) [0|65535] "mV"  PC
 SG_ CSC_Ucell_37_04 m12 : 16|16@1+ (1,0) [0|65535] "mV"  PC
 SG_ CSC_Ucell_38_04 m12 : 32|16@1+ (1,0) [0|65535] "mV"  PC
 SG_ CSC_Ucell_39_04 m12 : 48|16@1+ (1,0) [0|65535] "mV"  PC
 SG_ CSC_Ucell_40_04 m13 : 16|16@1+ (1,0) [0|65535] "mV"  PC
 SG_ CSC_Ucell_41_04 m13 : 32|16@1+ (1,0) [0|65535] "mV"  PC
 SG_ CSC_Ucell_42_04 m13 : 48|16@1+ (1,0) [0|65535] "mV"  PC
 SG_ CSC_Ucell_43_04 m14 : 16|16@1+ (1,0) [0|65535] "mV"  PC
 SG_ CSC_Ucell_44_04 m14 : 32|16@1+ (1,0) [0|65535] "mV"  PC
 SG_ CSC_Ucell_45_04 m14 : 48|16@1+ (1,0) [0|65535] "mV"  PC
 SG_ CSC_Ucell_46_04 m15 : 16|16@1+ (1,0) [0|65535] "mV"  PC
 SG_ CSC_Ucell_47_04 m15 : 32|16@1+ (1,0) [0|65535] "mV"  PC
 SG_ CSC_Ucell_48_04 m15 : 48|16@1+ (1,0) [0|65535] "mV"  PC
 SG_ CSC_Ucell_49_04 m16 : 16|16@1+ (1,0) [0|65535] "mV"  PC
 SG_ CSC_Ucell_50_04 m16 : 32|16@1+ (1,0) [0|65535] "mV"  PC
 SG_ CSC_Ucell_51_04 m16 : 48|16@1+ (1,0) [0|65535] "mV"  PC
 SG_ CSC_Ucell_52_04 m17 : 16|16@1+ (1,0) [0|65535] "mV"  PC
 SG_ CSC_Ucell_53_04 m17 : 32|16@1+ (1,0) [0|65535] "mV"  PC
 SG_ CSC_Ucell_54_04 m17 : 48|16@1+ (1,0) [0|65535] "mV"  PC
 SG_ CSC_Ucell_55_04 m18 : 16|16@1+ (1,0) [0|65535] "mV"  PC
 SG_ CSC_Ucell_56_04 m18 : 32|16@1+ (1,0) [0|65535] "mV"  PC
 SG_ CSC_Ucell_57_04 m18 : 48|16@1+ (1,0) [0|65535] ""  PC

BO_ 2400316997 S2P_Detail_Ucell1__05: 8 SBMU
 SG_ CSC_U_No_05 : 0|8@1+ (1,0) [0|255] ""  PC
 SG_ CSC_Ucell_Frame_Index_05 M : 8|8@1+ (1,0) [0|255] ""  PC
 SG_ CSC_Ucell_01_05 m0 : 16|16@1+ (1,0) [0|65535] "mV"  PC
 SG_ CSC_Ucell_02_05 m0 : 32|16@1+ (1,0) [0|65535] "mV"  PC
 SG_ CSC_Ucell_03_05 m0 : 48|16@1+ (1,0) [0|65535] "mV"  PC
 SG_ CSC_Ucell_04_05 m1 : 16|16@1+ (1,0) [0|65535] "mV"  PC
 SG_ CSC_Ucell_05_05 m1 : 32|16@1+ (1,0) [0|65535] "mV"  PC
 SG_ CSC_Ucell_06_05 m1 : 48|16@1+ (1,0) [0|65535] "mV"  PC
 SG_ CSC_Ucell_07_05 m2 : 16|16@1+ (1,0) [0|65535] "mV"  PC
 SG_ CSC_Ucell_08_05 m2 : 32|16@1+ (1,0) [0|65535] "mV"  PC
 SG_ CSC_Ucell_09_05 m2 : 48|16@1+ (1,0) [0|65535] "mV"  PC
 SG_ CSC_Ucell_10_05 m3 : 16|16@1+ (1,0) [0|65535] "mV"  PC
 SG_ CSC_Ucell_11_05 m3 : 32|16@1+ (1,0) [0|65535] "mV"  PC
 SG_ CSC_Ucell_12_05 m3 : 48|16@1+ (1,0) [0|65535] "mV"  PC
 SG_ CSC_Ucell_13_05 m4 : 16|16@1+ (1,0) [0|65535] "mV"  PC
 SG_ CSC_Ucell_14_05 m4 : 32|16@1+ (1,0) [0|65535] "mV"  PC
 SG_ CSC_Ucell_15_05 m4 : 48|16@1+ (1,0) [0|65535] "mV"  PC
 SG_ CSC_Ucell_16_05 m5 : 16|16@1+ (1,0) [0|65535] "mV"  PC
 SG_ CSC_Ucell_17_05 m5 : 32|16@1+ (1,0) [0|65535] "mV"  PC
 SG_ CSC_Ucell_18_05 m5 : 48|16@1+ (1,0) [0|65535] "mV"  PC
 SG_ CSC_Ucell_19_05 m6 : 16|16@1+ (1,0) [0|65535] "mV"  PC
 SG_ CSC_Ucell_20_05 m6 : 32|16@1+ (1,0) [0|65535] "mV"  PC
 SG_ CSC_Ucell_21_05 m6 : 48|16@1+ (1,0) [0|65535] "mV"  PC
 SG_ CSC_Ucell_22_05 m7 : 16|16@1+ (1,0) [0|65535] "mV"  PC
 SG_ CSC_Ucell_23_05 m7 : 32|16@1+ (1,0) [0|65535] "mV"  PC
 SG_ CSC_Ucell_24_05 m7 : 48|16@1+ (1,0) [0|65535] "mV"  PC
 SG_ CSC_Ucell_25_05 m8 : 16|16@1+ (1,0) [0|65535] "mV"  PC
 SG_ CSC_Ucell_26_05 m8 : 32|16@1+ (1,0) [0|65535] "mV"  PC
 SG_ CSC_Ucell_27_05 m8 : 48|16@1+ (1,0) [0|65535] "mV"  PC
 SG_ CSC_Ucell_28_05 m9 : 16|16@1+ (1,0) [0|65535] "mV"  PC
 SG_ CSC_Ucell_29_05 m9 : 32|16@1+ (1,0) [0|65535] "mV"  PC
 SG_ CSC_Ucell_30_05 m9 : 48|16@1+ (1,0) [0|65535] "mV"  PC
 SG_ CSC_Ucell_31_05 m10 : 16|16@1+ (1,0) [0|65535] "mV"  PC
 SG_ CSC_Ucell_32_05 m10 : 32|16@1+ (1,0) [0|65535] "mV"  PC
 SG_ CSC_Ucell_33_05 m10 : 48|16@1+ (1,0) [0|65535] "mV"  PC
 SG_ CSC_Ucell_34_05 m11 : 16|16@1+ (1,0) [0|65535] "mV"  PC
 SG_ CSC_Ucell_35_05 m11 : 32|16@1+ (1,0) [0|65535] "mV"  PC
 SG_ CSC_Ucell_36_05 m11 : 48|16@1+ (1,0) [0|65535] "mV"  PC
 SG_ CSC_Ucell_37_05 m12 : 16|16@1+ (1,0) [0|65535] "mV"  PC
 SG_ CSC_Ucell_38_05 m12 : 32|16@1+ (1,0) [0|65535] "mV"  PC
 SG_ CSC_Ucell_39_05 m12 : 48|16@1+ (1,0) [0|65535] "mV"  PC
 SG_ CSC_Ucell_40_05 m13 : 16|16@1+ (1,0) [0|65535] "mV"  PC
 SG_ CSC_Ucell_41_05 m13 : 32|16@1+ (1,0) [0|65535] "mV"  PC
 SG_ CSC_Ucell_42_05 m13 : 48|16@1+ (1,0) [0|65535] "mV"  PC
 SG_ CSC_Ucell_43_05 m14 : 16|16@1+ (1,0) [0|65535] "mV"  PC
 SG_ CSC_Ucell_44_05 m14 : 32|16@1+ (1,0) [0|65535] "mV"  PC
 SG_ CSC_Ucell_45_05 m14 : 48|16@1+ (1,0) [0|65535] "mV"  PC
 SG_ CSC_Ucell_46_05 m15 : 16|16@1+ (1,0) [0|65535] "mV"  PC
 SG_ CSC_Ucell_47_05 m15 : 32|16@1+ (1,0) [0|65535] "mV"  PC
 SG_ CSC_Ucell_48_05 m15 : 48|16@1+ (1,0) [0|65535] "mV"  PC
 SG_ CSC_Ucell_49_05 m16 : 16|16@1+ (1,0) [0|65535] "mV"  PC
 SG_ CSC_Ucell_50_05 m16 : 32|16@1+ (1,0) [0|65535] "mV"  PC
 SG_ CSC_Ucell_51_05 m16 : 48|16@1+ (1,0) [0|65535] "mV"  PC
 SG_ CSC_Ucell_52_05 m17 : 16|16@1+ (1,0) [0|65535] "mV"  PC
 SG_ CSC_Ucell_53_05 m17 : 32|16@1+ (1,0) [0|65535] "mV"  PC
 SG_ CSC_Ucell_54_05 m17 : 48|16@1+ (1,0) [0|65535] "mV"  PC
 SG_ CSC_Ucell_55_05 m18 : 16|16@1+ (1,0) [0|65535] "mV"  PC
 SG_ CSC_Ucell_56_05 m18 : 32|16@1+ (1,0) [0|65535] "mV"  PC
 SG_ CSC_Ucell_57_05 m18 : 48|16@1+ (1,0) [0|65535] ""  PC

BO_ 2400316998 S2P_Detail_Ucell1__06: 8 SBMU
 SG_ CSC_U_No_06 : 0|8@1+ (1,0) [0|255] ""  PC
 SG_ CSC_Ucell_Frame_Index_06 M : 8|8@1+ (1,0) [0|255] ""  PC
 SG_ CSC_Ucell_01_06 m0 : 16|16@1+ (1,0) [0|65535] "mV"  PC
 SG_ CSC_Ucell_02_06 m0 : 32|16@1+ (1,0) [0|65535] "mV"  PC
 SG_ CSC_Ucell_03_06 m0 : 48|16@1+ (1,0) [0|65535] "mV"  PC
 SG_ CSC_Ucell_04_06 m1 : 16|16@1+ (1,0) [0|65535] "mV"  PC
 SG_ CSC_Ucell_05_06 m1 : 32|16@1+ (1,0) [0|65535] "mV"  PC
 SG_ CSC_Ucell_06_06 m1 : 48|16@1+ (1,0) [0|65535] "mV"  PC
 SG_ CSC_Ucell_07_06 m2 : 16|16@1+ (1,0) [0|65535] "mV"  PC
 SG_ CSC_Ucell_08_06 m2 : 32|16@1+ (1,0) [0|65535] "mV"  PC
 SG_ CSC_Ucell_09_06 m2 : 48|16@1+ (1,0) [0|65535] "mV"  PC
 SG_ CSC_Ucell_10_06 m3 : 16|16@1+ (1,0) [0|65535] "mV"  PC
 SG_ CSC_Ucell_11_06 m3 : 32|16@1+ (1,0) [0|65535] "mV"  PC
 SG_ CSC_Ucell_12_06 m3 : 48|16@1+ (1,0) [0|65535] "mV"  PC
 SG_ CSC_Ucell_13_06 m4 : 16|16@1+ (1,0) [0|65535] "mV"  PC
 SG_ CSC_Ucell_14_06 m4 : 32|16@1+ (1,0) [0|65535] "mV"  PC
 SG_ CSC_Ucell_15_06 m4 : 48|16@1+ (1,0) [0|65535] "mV"  PC
 SG_ CSC_Ucell_16_06 m5 : 16|16@1+ (1,0) [0|65535] "mV"  PC
 SG_ CSC_Ucell_17_06 m5 : 32|16@1+ (1,0) [0|65535] "mV"  PC
 SG_ CSC_Ucell_18_06 m5 : 48|16@1+ (1,0) [0|65535] "mV"  PC
 SG_ CSC_Ucell_19_06 m6 : 16|16@1+ (1,0) [0|65535] "mV"  PC
 SG_ CSC_Ucell_20_06 m6 : 32|16@1+ (1,0) [0|65535] "mV"  PC
 SG_ CSC_Ucell_21_06 m6 : 48|16@1+ (1,0) [0|65535] "mV"  PC
 SG_ CSC_Ucell_22_06 m7 : 16|16@1+ (1,0) [0|65535] "mV"  PC
 SG_ CSC_Ucell_23_06 m7 : 32|16@1+ (1,0) [0|65535] "mV"  PC
 SG_ CSC_Ucell_24_06 m7 : 48|16@1+ (1,0) [0|65535] "mV"  PC
 SG_ CSC_Ucell_25_06 m8 : 16|16@1+ (1,0) [0|65535] "mV"  PC
 SG_ CSC_Ucell_26_06 m8 : 32|16@1+ (1,0) [0|65535] "mV"  PC
 SG_ CSC_Ucell_27_06 m8 : 48|16@1+ (1,0) [0|65535] "mV"  PC
 SG_ CSC_Ucell_28_06 m9 : 16|16@1+ (1,0) [0|65535] "mV"  PC
 SG_ CSC_Ucell_29_06 m9 : 32|16@1+ (1,0) [0|65535] "mV"  PC
 SG_ CSC_Ucell_30_06 m9 : 48|16@1+ (1,0) [0|65535] "mV"  PC
 SG_ CSC_Ucell_31_06 m10 : 16|16@1+ (1,0) [0|65535] "mV"  PC
 SG_ CSC_Ucell_32_06 m10 : 32|16@1+ (1,0) [0|65535] "mV"  PC
 SG_ CSC_Ucell_33_06 m10 : 48|16@1+ (1,0) [0|65535] "mV"  PC
 SG_ CSC_Ucell_34_06 m11 : 16|16@1+ (1,0) [0|65535] "mV"  PC
 SG_ CSC_Ucell_35_06 m11 : 32|16@1+ (1,0) [0|65535] "mV"  PC
 SG_ CSC_Ucell_36_06 m11 : 48|16@1+ (1,0) [0|65535] "mV"  PC
 SG_ CSC_Ucell_37_06 m12 : 16|16@1+ (1,0) [0|65535] "mV"  PC
 SG_ CSC_Ucell_38_06 m12 : 32|16@1+ (1,0) [0|65535] "mV"  PC
 SG_ CSC_Ucell_39_06 m12 : 48|16@1+ (1,0) [0|65535] "mV"  PC
 SG_ CSC_Ucell_40_06 m13 : 16|16@1+ (1,0) [0|65535] "mV"  PC
 SG_ CSC_Ucell_41_06 m13 : 32|16@1+ (1,0) [0|65535] "mV"  PC
 SG_ CSC_Ucell_42_06 m13 : 48|16@1+ (1,0) [0|65535] "mV"  PC
 SG_ CSC_Ucell_43_06 m14 : 16|16@1+ (1,0) [0|65535] "mV"  PC
 SG_ CSC_Ucell_44_06 m14 : 32|16@1+ (1,0) [0|65535] "mV"  PC
 SG_ CSC_Ucell_45_06 m14 : 48|16@1+ (1,0) [0|65535] "mV"  PC
 SG_ CSC_Ucell_46_06 m15 : 16|16@1+ (1,0) [0|65535] "mV"  PC
 SG_ CSC_Ucell_47_06 m15 : 32|16@1+ (1,0) [0|65535] "mV"  PC
 SG_ CSC_Ucell_48_06 m15 : 48|16@1+ (1,0) [0|65535] "mV"  PC
 SG_ CSC_Ucell_49_06 m16 : 16|16@1+ (1,0) [0|65535] "mV"  PC
 SG_ CSC_Ucell_50_06 m16 : 32|16@1+ (1,0) [0|65535] "mV"  PC
 SG_ CSC_Ucell_51_06 m16 : 48|16@1+ (1,0) [0|65535] "mV"  PC
 SG_ CSC_Ucell_52_06 m17 : 16|16@1+ (1,0) [0|65535] "mV"  PC
 SG_ CSC_Ucell_53_06 m17 : 32|16@1+ (1,0) [0|65535] "mV"  PC
 SG_ CSC_Ucell_54_06 m17 : 48|16@1+ (1,0) [0|65535] "mV"  PC
 SG_ CSC_Ucell_55_06 m18 : 16|16@1+ (1,0) [0|65535] "mV"  PC
 SG_ CSC_Ucell_56_06 m18 : 32|16@1+ (1,0) [0|65535] "mV"  PC
 SG_ CSC_Ucell_57_06 m18 : 48|16@1+ (1,0) [0|65535] ""  PC

BO_ 2400316999 S2P_Detail_Ucell1__07: 8 SBMU
 SG_ CSC_U_No_07 : 0|8@1+ (1,0) [0|255] ""  PC
 SG_ CSC_Ucell_Frame_Index_07 M : 8|8@1+ (1,0) [0|255] ""  PC
 SG_ CSC_Ucell_01_07 m0 : 16|16@1+ (1,0) [0|65535] "mV"  PC
 SG_ CSC_Ucell_02_07 m0 : 32|16@1+ (1,0) [0|65535] "mV"  PC
 SG_ CSC_Ucell_03_07 m0 : 48|16@1+ (1,0) [0|65535] "mV"  PC
 SG_ CSC_Ucell_04_07 m1 : 16|16@1+ (1,0) [0|65535] "mV"  PC
 SG_ CSC_Ucell_05_07 m1 : 32|16@1+ (1,0) [0|65535] "mV"  PC
 SG_ CSC_Ucell_06_07 m1 : 48|16@1+ (1,0) [0|65535] "mV"  PC
 SG_ CSC_Ucell_07_07 m2 : 16|16@1+ (1,0) [0|65535] "mV"  PC
 SG_ CSC_Ucell_08_07 m2 : 32|16@1+ (1,0) [0|65535] "mV"  PC
 SG_ CSC_Ucell_09_07 m2 : 48|16@1+ (1,0) [0|65535] "mV"  PC
 SG_ CSC_Ucell_10_07 m3 : 16|16@1+ (1,0) [0|65535] "mV"  PC
 SG_ CSC_Ucell_11_07 m3 : 32|16@1+ (1,0) [0|65535] "mV"  PC
 SG_ CSC_Ucell_12_07 m3 : 48|16@1+ (1,0) [0|65535] "mV"  PC
 SG_ CSC_Ucell_13_07 m4 : 16|16@1+ (1,0) [0|65535] "mV"  PC
 SG_ CSC_Ucell_14_07 m4 : 32|16@1+ (1,0) [0|65535] "mV"  PC
 SG_ CSC_Ucell_15_07 m4 : 48|16@1+ (1,0) [0|65535] "mV"  PC
 SG_ CSC_Ucell_16_07 m5 : 16|16@1+ (1,0) [0|65535] "mV"  PC
 SG_ CSC_Ucell_17_07 m5 : 32|16@1+ (1,0) [0|65535] "mV"  PC
 SG_ CSC_Ucell_18_07 m5 : 48|16@1+ (1,0) [0|65535] "mV"  PC
 SG_ CSC_Ucell_19_07 m6 : 16|16@1+ (1,0) [0|65535] "mV"  PC
 SG_ CSC_Ucell_20_07 m6 : 32|16@1+ (1,0) [0|65535] "mV"  PC
 SG_ CSC_Ucell_21_07 m6 : 48|16@1+ (1,0) [0|65535] "mV"  PC
 SG_ CSC_Ucell_22_07 m7 : 16|16@1+ (1,0) [0|65535] "mV"  PC
 SG_ CSC_Ucell_23_07 m7 : 32|16@1+ (1,0) [0|65535] "mV"  PC
 SG_ CSC_Ucell_24_07 m7 : 48|16@1+ (1,0) [0|65535] "mV"  PC
 SG_ CSC_Ucell_25_07 m8 : 16|16@1+ (1,0) [0|65535] "mV"  PC
 SG_ CSC_Ucell_26_07 m8 : 32|16@1+ (1,0) [0|65535] "mV"  PC
 SG_ CSC_Ucell_27_07 m8 : 48|16@1+ (1,0) [0|65535] "mV"  PC
 SG_ CSC_Ucell_28_07 m9 : 16|16@1+ (1,0) [0|65535] "mV"  PC
 SG_ CSC_Ucell_29_07 m9 : 32|16@1+ (1,0) [0|65535] "mV"  PC
 SG_ CSC_Ucell_30_07 m9 : 48|16@1+ (1,0) [0|65535] "mV"  PC
 SG_ CSC_Ucell_31_07 m10 : 16|16@1+ (1,0) [0|65535] "mV"  PC
 SG_ CSC_Ucell_32_07 m10 : 32|16@1+ (1,0) [0|65535] "mV"  PC
 SG_ CSC_Ucell_33_07 m10 : 48|16@1+ (1,0) [0|65535] "mV"  PC
 SG_ CSC_Ucell_34_07 m11 : 16|16@1+ (1,0) [0|65535] "mV"  PC
 SG_ CSC_Ucell_35_07 m11 : 32|16@1+ (1,0) [0|65535] "mV"  PC
 SG_ CSC_Ucell_36_07 m11 : 48|16@1+ (1,0) [0|65535] "mV"  PC
 SG_ CSC_Ucell_37_07 m12 : 16|16@1+ (1,0) [0|65535] "mV"  PC
 SG_ CSC_Ucell_38_07 m12 : 32|16@1+ (1,0) [0|65535] "mV"  PC
 SG_ CSC_Ucell_39_07 m12 : 48|16@1+ (1,0) [0|65535] "mV"  PC
 SG_ CSC_Ucell_40_07 m13 : 16|16@1+ (1,0) [0|65535] "mV"  PC
 SG_ CSC_Ucell_41_07 m13 : 32|16@1+ (1,0) [0|65535] "mV"  PC
 SG_ CSC_Ucell_42_07 m13 : 48|16@1+ (1,0) [0|65535] "mV"  PC
 SG_ CSC_Ucell_43_07 m14 : 16|16@1+ (1,0) [0|65535] "mV"  PC
 SG_ CSC_Ucell_44_07 m14 : 32|16@1+ (1,0) [0|65535] "mV"  PC
 SG_ CSC_Ucell_45_07 m14 : 48|16@1+ (1,0) [0|65535] "mV"  PC
 SG_ CSC_Ucell_46_07 m15 : 16|16@1+ (1,0) [0|65535] "mV"  PC
 SG_ CSC_Ucell_47_07 m15 : 32|16@1+ (1,0) [0|65535] "mV"  PC
 SG_ CSC_Ucell_48_07 m15 : 48|16@1+ (1,0) [0|65535] "mV"  PC
 SG_ CSC_Ucell_49_07 m16 : 16|16@1+ (1,0) [0|65535] "mV"  PC
 SG_ CSC_Ucell_50_07 m16 : 32|16@1+ (1,0) [0|65535] "mV"  PC
 SG_ CSC_Ucell_51_07 m16 : 48|16@1+ (1,0) [0|65535] "mV"  PC
 SG_ CSC_Ucell_52_07 m17 : 16|16@1+ (1,0) [0|65535] "mV"  PC
 SG_ CSC_Ucell_53_07 m17 : 32|16@1+ (1,0) [0|65535] "mV"  PC
 SG_ CSC_Ucell_54_07 m17 : 48|16@1+ (1,0) [0|65535] "mV"  PC
 SG_ CSC_Ucell_55_07 m18 : 16|16@1+ (1,0) [0|65535] "mV"  PC
 SG_ CSC_Ucell_56_07 m18 : 32|16@1+ (1,0) [0|65535] "mV"  PC
 SG_ CSC_Ucell_57_07 m18 : 48|16@1+ (1,0) [0|65535] ""  PC

CM_ SG_ 2332753748 FireFault_Level1_20 "一级消防故障";
CM_ SG_ 2332753748 FireFault_Level2_20 "二级消防故障";
CM_ SG_ 2332753748 TempState_20 "温感状态";
CM_ SG_ 2332753748 FogState_20 "烟感状态";
CM_ SG_ 2332753748 AerosolState_20 "气溶胶状态";
CM_ SG_ 2332753748 AerosolFaultState_20 "气溶胶故障状态";
CM_ SG_ 2332753748 DoorState_20 "门禁状态";
CM_ SG_ 2332753748 ControlBoxFanState_20 "主控箱风机状态";
CM_ SG_ 2332753748 ControlBoxTempHighWarning_20 "主控箱高温告警";
CM_ SG_ 2332753748 PowerSWState_20 "单柜开关状态（门把手上的钥匙开关）";
CM_ SG_ 2332753748 FaultClearCommand_20 "故障清除指令";
CM_ SG_ 2332753749 FireFault_Level1_21 "一级消防故障";
CM_ SG_ 2332753749 FireFault_Level2_21 "二级消防故障";
CM_ SG_ 2332753749 TempState_21 "温感状态";
CM_ SG_ 2332753749 FogState_21 "烟感状态";
CM_ SG_ 2332753749 AerosolState_21 "气溶胶状态";
CM_ SG_ 2332753749 AerosolFaultState_21 "气溶胶故障状态";
CM_ SG_ 2332753749 DoorState_21 "门禁状态";
CM_ SG_ 2332753749 ControlBoxFanState_21 "主控箱风机状态";
CM_ SG_ 2332753749 ControlBoxTempHighWarning_21 "主控箱高温告警";
CM_ SG_ 2332753749 PowerSWState_21 "单柜开关状态（门把手上的钥匙开关）";
CM_ SG_ 2332753749 FaultClearCommand_21 "故障清除指令";
CM_ SG_ 2332753750 FireFault_Level1_22 "一级消防故障";
CM_ SG_ 2332753750 FireFault_Level2_22 "二级消防故障";
CM_ SG_ 2332753750 TempState_22 "温感状态";
CM_ SG_ 2332753750 FogState_22 "烟感状态";
CM_ SG_ 2332753750 AerosolState_22 "气溶胶状态";
CM_ SG_ 2332753750 AerosolFaultState_22 "气溶胶故障状态";
CM_ SG_ 2332753750 DoorState_22 "门禁状态";
CM_ SG_ 2332753750 ControlBoxFanState_22 "主控箱风机状态";
CM_ SG_ 2332753750 ControlBoxTempHighWarning_22 "主控箱高温告警";
CM_ SG_ 2332753750 PowerSWState_22 "单柜开关状态（门把手上的钥匙开关）";
CM_ SG_ 2332753750 FaultClearCommand_22 "故障清除指令";
CM_ SG_ 2332753751 FireFault_Level1_23 "一级消防故障";
CM_ SG_ 2332753751 FireFault_Level2_23 "二级消防故障";
CM_ SG_ 2332753751 TempState_23 "温感状态";
CM_ SG_ 2332753751 FogState_23 "烟感状态";
CM_ SG_ 2332753751 AerosolState_23 "气溶胶状态";
CM_ SG_ 2332753751 AerosolFaultState_23 "气溶胶故障状态";
CM_ SG_ 2332753751 DoorState_23 "门禁状态";
CM_ SG_ 2332753751 ControlBoxFanState_23 "主控箱风机状态";
CM_ SG_ 2332753751 ControlBoxTempHighWarning_23 "主控箱高温告警";
CM_ SG_ 2332753751 PowerSWState_23 "单柜开关状态（门把手上的钥匙开关）";
CM_ SG_ 2332753751 FaultClearCommand_23 "故障清除指令";
CM_ SG_ 2332753752 FireFault_Level1_24 "一级消防故障";
CM_ SG_ 2332753752 FireFault_Level2_24 "二级消防故障";
CM_ SG_ 2332753752 TempState_24 "温感状态";
CM_ SG_ 2332753752 FogState_24 "烟感状态";
CM_ SG_ 2332753752 AerosolState_24 "气溶胶状态";
CM_ SG_ 2332753752 AerosolFaultState_24 "气溶胶故障状态";
CM_ SG_ 2332753752 DoorState_24 "门禁状态";
CM_ SG_ 2332753752 ControlBoxFanState_24 "主控箱风机状态";
CM_ SG_ 2332753752 ControlBoxTempHighWarning_24 "主控箱高温告警";
CM_ SG_ 2332753752 PowerSWState_24 "单柜开关状态（门把手上的钥匙开关）";
CM_ SG_ 2332753752 FaultClearCommand_24 "故障清除指令";
CM_ SG_ 2332753753 FireFault_Level1_25 "一级消防故障";
CM_ SG_ 2332753753 FireFault_Level2_25 "二级消防故障";
CM_ SG_ 2332753753 TempState_25 "温感状态";
CM_ SG_ 2332753753 FogState_25 "烟感状态";
CM_ SG_ 2332753753 AerosolState_25 "气溶胶状态";
CM_ SG_ 2332753753 AerosolFaultState_25 "气溶胶故障状态";
CM_ SG_ 2332753753 DoorState_25 "门禁状态";
CM_ SG_ 2332753753 ControlBoxFanState_25 "主控箱风机状态";
CM_ SG_ 2332753753 ControlBoxTempHighWarning_25 "主控箱高温告警";
CM_ SG_ 2332753753 PowerSWState_25 "单柜开关状态（门把手上的钥匙开关）";
CM_ SG_ 2332753753 FaultClearCommand_25 "故障清除指令";
CM_ SG_ 2332753754 FireFault_Level1_26 "一级消防故障";
CM_ SG_ 2332753754 FireFault_Level2_26 "二级消防故障";
CM_ SG_ 2332753754 TempState_26 "温感状态";
CM_ SG_ 2332753754 FogState_26 "烟感状态";
CM_ SG_ 2332753754 AerosolState_26 "气溶胶状态";
CM_ SG_ 2332753754 AerosolFaultState_26 "气溶胶故障状态";
CM_ SG_ 2332753754 DoorState_26 "门禁状态";
CM_ SG_ 2332753754 ControlBoxFanState_26 "主控箱风机状态";
CM_ SG_ 2332753754 ControlBoxTempHighWarning_26 "主控箱高温告警";
CM_ SG_ 2332753754 PowerSWState_26 "单柜开关状态（门把手上的钥匙开关）";
CM_ SG_ 2332753754 FaultClearCommand_26 "故障清除指令";
CM_ SG_ 2332753755 FireFault_Level1_27 "一级消防故障";
CM_ SG_ 2332753755 FireFault_Level2_27 "二级消防故障";
CM_ SG_ 2332753755 TempState_27 "温感状态";
CM_ SG_ 2332753755 FogState_27 "烟感状态";
CM_ SG_ 2332753755 AerosolState_27 "气溶胶状态";
CM_ SG_ 2332753755 AerosolFaultState_27 "气溶胶故障状态";
CM_ SG_ 2332753755 DoorState_27 "门禁状态";
CM_ SG_ 2332753755 ControlBoxFanState_27 "主控箱风机状态";
CM_ SG_ 2332753755 ControlBoxTempHighWarning_27 "主控箱高温告警";
CM_ SG_ 2332753755 PowerSWState_27 "单柜开关状态（门把手上的钥匙开关）";
CM_ SG_ 2332753755 FaultClearCommand_27 "故障清除指令";
CM_ SG_ 2332753756 FireFault_Level1_28 "一级消防故障";
CM_ SG_ 2332753756 FireFault_Level2_28 "二级消防故障";
CM_ SG_ 2332753756 TempState_28 "温感状态";
CM_ SG_ 2332753756 FogState_28 "烟感状态";
CM_ SG_ 2332753756 AerosolState_28 "气溶胶状态";
CM_ SG_ 2332753756 AerosolFaultState_28 "气溶胶故障状态";
CM_ SG_ 2332753756 DoorState_28 "门禁状态";
CM_ SG_ 2332753756 ControlBoxFanState_28 "主控箱风机状态";
CM_ SG_ 2332753756 ControlBoxTempHighWarning_28 "主控箱高温告警";
CM_ SG_ 2332753756 PowerSWState_28 "单柜开关状态（门把手上的钥匙开关）";
CM_ SG_ 2332753756 FaultClearCommand_28 "故障清除指令";
CM_ SG_ 2332753757 FireFault_Level1_29 "一级消防故障";
CM_ SG_ 2332753757 FireFault_Level2_29 "二级消防故障";
CM_ SG_ 2332753757 TempState_29 "温感状态";
CM_ SG_ 2332753757 FogState_29 "烟感状态";
CM_ SG_ 2332753757 AerosolState_29 "气溶胶状态";
CM_ SG_ 2332753757 AerosolFaultState_29 "气溶胶故障状态";
CM_ SG_ 2332753757 DoorState_29 "门禁状态";
CM_ SG_ 2332753757 ControlBoxFanState_29 "主控箱风机状态";
CM_ SG_ 2332753757 ControlBoxTempHighWarning_29 "主控箱高温告警";
CM_ SG_ 2332753757 PowerSWState_29 "单柜开关状态（门把手上的钥匙开关）";
CM_ SG_ 2332753757 FaultClearCommand_29 "故障清除指令";
CM_ SG_ 2332753758 FireFault_Level1_30 "一级消防故障";
CM_ SG_ 2332753758 FireFault_Level2_30 "二级消防故障";
CM_ SG_ 2332753758 TempState_30 "温感状态";
CM_ SG_ 2332753758 FogState_30 "烟感状态";
CM_ SG_ 2332753758 AerosolState_30 "气溶胶状态";
CM_ SG_ 2332753758 AerosolFaultState_30 "气溶胶故障状态";
CM_ SG_ 2332753758 DoorState_30 "门禁状态";
CM_ SG_ 2332753758 ControlBoxFanState_30 "主控箱风机状态";
CM_ SG_ 2332753758 ControlBoxTempHighWarning_30 "主控箱高温告警";
CM_ SG_ 2332753758 PowerSWState_30 "单柜开关状态（门把手上的钥匙开关）";
CM_ SG_ 2332753758 FaultClearCommand_30 "故障清除指令";
CM_ SG_ 2332753759 FireFault_Level1_31 "一级消防故障";
CM_ SG_ 2332753759 FireFault_Level2_31 "二级消防故障";
CM_ SG_ 2332753759 TempState_31 "温感状态";
CM_ SG_ 2332753759 FogState_31 "烟感状态";
CM_ SG_ 2332753759 AerosolState_31 "气溶胶状态";
CM_ SG_ 2332753759 AerosolFaultState_31 "气溶胶故障状态";
CM_ SG_ 2332753759 DoorState_31 "门禁状态";
CM_ SG_ 2332753759 ControlBoxFanState_31 "主控箱风机状态";
CM_ SG_ 2332753759 ControlBoxTempHighWarning_31 "主控箱高温告警";
CM_ SG_ 2332753759 PowerSWState_31 "单柜开关状态（门把手上的钥匙开关）";
CM_ SG_ 2332753759 FaultClearCommand_31 "故障清除指令";
CM_ SG_ 2332753760 FireFault_Level1_32 "一级消防故障";
CM_ SG_ 2332753760 FireFault_Level2_32 "二级消防故障";
CM_ SG_ 2332753760 TempState_32 "温感状态";
CM_ SG_ 2332753760 FogState_32 "烟感状态";
CM_ SG_ 2332753760 AerosolState_32 "气溶胶状态";
CM_ SG_ 2332753760 AerosolFaultState_32 "气溶胶故障状态";
CM_ SG_ 2332753760 DoorState_32 "门禁状态";
CM_ SG_ 2332753760 ControlBoxFanState_32 "主控箱风机状态";
CM_ SG_ 2332753760 ControlBoxTempHighWarning_32 "主控箱高温告警";
CM_ SG_ 2332753760 PowerSWState_32 "单柜开关状态（门把手上的钥匙开关）";
CM_ SG_ 2332753760 FaultClearCommand_32 "故障清除指令";
CM_ SG_ 2332753761 FireFault_Level1_33 "一级消防故障";
CM_ SG_ 2332753761 FireFault_Level2_33 "二级消防故障";
CM_ SG_ 2332753761 TempState_33 "温感状态";
CM_ SG_ 2332753761 FogState_33 "烟感状态";
CM_ SG_ 2332753761 AerosolState_33 "气溶胶状态";
CM_ SG_ 2332753761 AerosolFaultState_33 "气溶胶故障状态";
CM_ SG_ 2332753761 DoorState_33 "门禁状态";
CM_ SG_ 2332753761 ControlBoxFanState_33 "主控箱风机状态";
CM_ SG_ 2332753761 ControlBoxTempHighWarning_33 "主控箱高温告警";
CM_ SG_ 2332753761 PowerSWState_33 "单柜开关状态（门把手上的钥匙开关）";
CM_ SG_ 2332753761 FaultClearCommand_33 "故障清除指令";
CM_ SG_ 2332753762 FireFault_Level1_34 "一级消防故障";
CM_ SG_ 2332753762 FireFault_Level2_34 "二级消防故障";
CM_ SG_ 2332753762 TempState_34 "温感状态";
CM_ SG_ 2332753762 FogState_34 "烟感状态";
CM_ SG_ 2332753762 AerosolState_34 "气溶胶状态";
CM_ SG_ 2332753762 AerosolFaultState_34 "气溶胶故障状态";
CM_ SG_ 2332753762 DoorState_34 "门禁状态";
CM_ SG_ 2332753762 ControlBoxFanState_34 "主控箱风机状态";
CM_ SG_ 2332753762 ControlBoxTempHighWarning_34 "主控箱高温告警";
CM_ SG_ 2332753762 PowerSWState_34 "单柜开关状态（门把手上的钥匙开关）";
CM_ SG_ 2332753762 FaultClearCommand_34 "故障清除指令";
CM_ SG_ 2332753763 FireFault_Level1_35 "一级消防故障";
CM_ SG_ 2332753763 FireFault_Level2_35 "二级消防故障";
CM_ SG_ 2332753763 TempState_35 "温感状态";
CM_ SG_ 2332753763 FogState_35 "烟感状态";
CM_ SG_ 2332753763 AerosolState_35 "气溶胶状态";
CM_ SG_ 2332753763 AerosolFaultState_35 "气溶胶故障状态";
CM_ SG_ 2332753763 DoorState_35 "门禁状态";
CM_ SG_ 2332753763 ControlBoxFanState_35 "主控箱风机状态";
CM_ SG_ 2332753763 ControlBoxTempHighWarning_35 "主控箱高温告警";
CM_ SG_ 2332753763 PowerSWState_35 "单柜开关状态（门把手上的钥匙开关）";
CM_ SG_ 2332753763 FaultClearCommand_35 "故障清除指令";
CM_ SG_ 2332753764 FireFault_Level1_36 "一级消防故障";
CM_ SG_ 2332753764 FireFault_Level2_36 "二级消防故障";
CM_ SG_ 2332753764 TempState_36 "温感状态";
CM_ SG_ 2332753764 FogState_36 "烟感状态";
CM_ SG_ 2332753764 AerosolState_36 "气溶胶状态";
CM_ SG_ 2332753764 AerosolFaultState_36 "气溶胶故障状态";
CM_ SG_ 2332753764 DoorState_36 "门禁状态";
CM_ SG_ 2332753764 ControlBoxFanState_36 "主控箱风机状态";
CM_ SG_ 2332753764 ControlBoxTempHighWarning_36 "主控箱高温告警";
CM_ SG_ 2332753764 PowerSWState_36 "单柜开关状态（门把手上的钥匙开关）";
CM_ SG_ 2332753764 FaultClearCommand_36 "故障清除指令";
CM_ SG_ 2332753765 FireFault_Level1_37 "一级消防故障";
CM_ SG_ 2332753765 FireFault_Level2_37 "二级消防故障";
CM_ SG_ 2332753765 TempState_37 "温感状态";
CM_ SG_ 2332753765 FogState_37 "烟感状态";
CM_ SG_ 2332753765 AerosolState_37 "气溶胶状态";
CM_ SG_ 2332753765 AerosolFaultState_37 "气溶胶故障状态";
CM_ SG_ 2332753765 DoorState_37 "门禁状态";
CM_ SG_ 2332753765 ControlBoxFanState_37 "主控箱风机状态";
CM_ SG_ 2332753765 ControlBoxTempHighWarning_37 "主控箱高温告警";
CM_ SG_ 2332753765 PowerSWState_37 "单柜开关状态（门把手上的钥匙开关）";
CM_ SG_ 2332753765 FaultClearCommand_37 "故障清除指令";
CM_ SG_ 2332753766 FireFault_Level1_38 "一级消防故障";
CM_ SG_ 2332753766 FireFault_Level2_38 "二级消防故障";
CM_ SG_ 2332753766 TempState_38 "温感状态";
CM_ SG_ 2332753766 FogState_38 "烟感状态";
CM_ SG_ 2332753766 AerosolState_38 "气溶胶状态";
CM_ SG_ 2332753766 AerosolFaultState_38 "气溶胶故障状态";
CM_ SG_ 2332753766 DoorState_38 "门禁状态";
CM_ SG_ 2332753766 ControlBoxFanState_38 "主控箱风机状态";
CM_ SG_ 2332753766 ControlBoxTempHighWarning_38 "主控箱高温告警";
CM_ SG_ 2332753766 PowerSWState_38 "单柜开关状态（门把手上的钥匙开关）";
CM_ SG_ 2332753766 FaultClearCommand_38 "故障清除指令";
CM_ SG_ 2332753767 FireFault_Level1_39 "一级消防故障";
CM_ SG_ 2332753767 FireFault_Level2_39 "二级消防故障";
CM_ SG_ 2332753767 TempState_39 "温感状态";
CM_ SG_ 2332753767 FogState_39 "烟感状态";
CM_ SG_ 2332753767 AerosolState_39 "气溶胶状态";
CM_ SG_ 2332753767 AerosolFaultState_39 "气溶胶故障状态";
CM_ SG_ 2332753767 DoorState_39 "门禁状态";
CM_ SG_ 2332753767 ControlBoxFanState_39 "主控箱风机状态";
CM_ SG_ 2332753767 ControlBoxTempHighWarning_39 "主控箱高温告警";
CM_ SG_ 2332753767 PowerSWState_39 "单柜开关状态（门把手上的钥匙开关）";
CM_ SG_ 2332753767 FaultClearCommand_39 "故障清除指令";
CM_ SG_ 2332753768 FireFault_Level1_40 "一级消防故障";
CM_ SG_ 2332753768 FireFault_Level2_40 "二级消防故障";
CM_ SG_ 2332753768 TempState_40 "温感状态";
CM_ SG_ 2332753768 FogState_40 "烟感状态";
CM_ SG_ 2332753768 AerosolState_40 "气溶胶状态";
CM_ SG_ 2332753768 AerosolFaultState_40 "气溶胶故障状态";
CM_ SG_ 2332753768 DoorState_40 "门禁状态";
CM_ SG_ 2332753768 ControlBoxFanState_40 "主控箱风机状态";
CM_ SG_ 2332753768 ControlBoxTempHighWarning_40 "主控箱高温告警";
CM_ SG_ 2332753768 PowerSWState_40 "单柜开关状态（门把手上的钥匙开关）";
CM_ SG_ 2332753768 FaultClearCommand_40 "故障清除指令";
CM_ SG_ 2332753769 FireFault_Level1_41 "一级消防故障";
CM_ SG_ 2332753769 FireFault_Level2_41 "二级消防故障";
CM_ SG_ 2332753769 TempState_41 "温感状态";
CM_ SG_ 2332753769 FogState_41 "烟感状态";
CM_ SG_ 2332753769 AerosolState_41 "气溶胶状态";
CM_ SG_ 2332753769 AerosolFaultState_41 "气溶胶故障状态";
CM_ SG_ 2332753769 DoorState_41 "门禁状态";
CM_ SG_ 2332753769 ControlBoxFanState_41 "主控箱风机状态";
CM_ SG_ 2332753769 ControlBoxTempHighWarning_41 "主控箱高温告警";
CM_ SG_ 2332753769 PowerSWState_41 "单柜开关状态（门把手上的钥匙开关）";
CM_ SG_ 2332753769 FaultClearCommand_41 "故障清除指令";
CM_ SG_ 2332753770 FireFault_Level1_42 "一级消防故障";
CM_ SG_ 2332753770 FireFault_Level2_42 "二级消防故障";
CM_ SG_ 2332753770 TempState_42 "温感状态";
CM_ SG_ 2332753770 FogState_42 "烟感状态";
CM_ SG_ 2332753770 AerosolState_42 "气溶胶状态";
CM_ SG_ 2332753770 AerosolFaultState_42 "气溶胶故障状态";
CM_ SG_ 2332753770 DoorState_42 "门禁状态";
CM_ SG_ 2332753770 ControlBoxFanState_42 "主控箱风机状态";
CM_ SG_ 2332753770 ControlBoxTempHighWarning_42 "主控箱高温告警";
CM_ SG_ 2332753770 PowerSWState_42 "单柜开关状态（门把手上的钥匙开关）";
CM_ SG_ 2332753770 FaultClearCommand_42 "故障清除指令";
CM_ SG_ 2332753771 FireFault_Level1_43 "一级消防故障";
CM_ SG_ 2332753771 FireFault_Level2_43 "二级消防故障";
CM_ SG_ 2332753771 TempState_43 "温感状态";
CM_ SG_ 2332753771 FogState_43 "烟感状态";
CM_ SG_ 2332753771 AerosolState_43 "气溶胶状态";
CM_ SG_ 2332753771 AerosolFaultState_43 "气溶胶故障状态";
CM_ SG_ 2332753771 DoorState_43 "门禁状态";
CM_ SG_ 2332753771 ControlBoxFanState_43 "主控箱风机状态";
CM_ SG_ 2332753771 ControlBoxTempHighWarning_43 "主控箱高温告警";
CM_ SG_ 2332753771 PowerSWState_43 "单柜开关状态（门把手上的钥匙开关）";
CM_ SG_ 2332753771 FaultClearCommand_43 "故障清除指令";
CM_ SG_ 2332753772 FireFault_Level1_44 "一级消防故障";
CM_ SG_ 2332753772 FireFault_Level2_44 "二级消防故障";
CM_ SG_ 2332753772 TempState_44 "温感状态";
CM_ SG_ 2332753772 FogState_44 "烟感状态";
CM_ SG_ 2332753772 AerosolState_44 "气溶胶状态";
CM_ SG_ 2332753772 AerosolFaultState_44 "气溶胶故障状态";
CM_ SG_ 2332753772 DoorState_44 "门禁状态";
CM_ SG_ 2332753772 ControlBoxFanState_44 "主控箱风机状态";
CM_ SG_ 2332753772 ControlBoxTempHighWarning_44 "主控箱高温告警";
CM_ SG_ 2332753772 PowerSWState_44 "单柜开关状态（门把手上的钥匙开关）";
CM_ SG_ 2332753772 FaultClearCommand_44 "故障清除指令";
CM_ SG_ 2332753773 FireFault_Level1_45 "一级消防故障";
CM_ SG_ 2332753773 FireFault_Level2_45 "二级消防故障";
CM_ SG_ 2332753773 TempState_45 "温感状态";
CM_ SG_ 2332753773 FogState_45 "烟感状态";
CM_ SG_ 2332753773 AerosolState_45 "气溶胶状态";
CM_ SG_ 2332753773 AerosolFaultState_45 "气溶胶故障状态";
CM_ SG_ 2332753773 DoorState_45 "门禁状态";
CM_ SG_ 2332753773 ControlBoxFanState_45 "主控箱风机状态";
CM_ SG_ 2332753773 ControlBoxTempHighWarning_45 "主控箱高温告警";
CM_ SG_ 2332753773 PowerSWState_45 "单柜开关状态（门把手上的钥匙开关）";
CM_ SG_ 2332753773 FaultClearCommand_45 "故障清除指令";
CM_ SG_ 2332753774 FireFault_Level1_46 "一级消防故障";
CM_ SG_ 2332753774 FireFault_Level2_46 "二级消防故障";
CM_ SG_ 2332753774 TempState_46 "温感状态";
CM_ SG_ 2332753774 FogState_46 "烟感状态";
CM_ SG_ 2332753774 AerosolState_46 "气溶胶状态";
CM_ SG_ 2332753774 AerosolFaultState_46 "气溶胶故障状态";
CM_ SG_ 2332753774 DoorState_46 "门禁状态";
CM_ SG_ 2332753774 ControlBoxFanState_46 "主控箱风机状态";
CM_ SG_ 2332753774 ControlBoxTempHighWarning_46 "主控箱高温告警";
CM_ SG_ 2332753774 PowerSWState_46 "单柜开关状态（门把手上的钥匙开关）";
CM_ SG_ 2332753774 FaultClearCommand_46 "故障清除指令";
CM_ SG_ 2332753775 FireFault_Level1_47 "一级消防故障";
CM_ SG_ 2332753775 FireFault_Level2_47 "二级消防故障";
CM_ SG_ 2332753775 TempState_47 "温感状态";
CM_ SG_ 2332753775 FogState_47 "烟感状态";
CM_ SG_ 2332753775 AerosolState_47 "气溶胶状态";
CM_ SG_ 2332753775 AerosolFaultState_47 "气溶胶故障状态";
CM_ SG_ 2332753775 DoorState_47 "门禁状态";
CM_ SG_ 2332753775 ControlBoxFanState_47 "主控箱风机状态";
CM_ SG_ 2332753775 ControlBoxTempHighWarning_47 "主控箱高温告警";
CM_ SG_ 2332753775 PowerSWState_47 "单柜开关状态（门把手上的钥匙开关）";
CM_ SG_ 2332753775 FaultClearCommand_47 "故障清除指令";
CM_ SG_ 2332753776 FireFault_Level1_48 "一级消防故障";
CM_ SG_ 2332753776 FireFault_Level2_48 "二级消防故障";
CM_ SG_ 2332753776 TempState_48 "温感状态";
CM_ SG_ 2332753776 FogState_48 "烟感状态";
CM_ SG_ 2332753776 AerosolState_48 "气溶胶状态";
CM_ SG_ 2332753776 AerosolFaultState_48 "气溶胶故障状态";
CM_ SG_ 2332753776 DoorState_48 "门禁状态";
CM_ SG_ 2332753776 ControlBoxFanState_48 "主控箱风机状态";
CM_ SG_ 2332753776 ControlBoxTempHighWarning_48 "主控箱高温告警";
CM_ SG_ 2332753776 PowerSWState_48 "单柜开关状态（门把手上的钥匙开关）";
CM_ SG_ 2332753776 FaultClearCommand_48 "故障清除指令";
CM_ SG_ 2332753777 FireFault_Level1_49 "一级消防故障";
CM_ SG_ 2332753777 FireFault_Level2_49 "二级消防故障";
CM_ SG_ 2332753777 TempState_49 "温感状态";
CM_ SG_ 2332753777 FogState_49 "烟感状态";
CM_ SG_ 2332753777 AerosolState_49 "气溶胶状态";
CM_ SG_ 2332753777 AerosolFaultState_49 "气溶胶故障状态";
CM_ SG_ 2332753777 DoorState_49 "门禁状态";
CM_ SG_ 2332753777 ControlBoxFanState_49 "主控箱风机状态";
CM_ SG_ 2332753777 ControlBoxTempHighWarning_49 "主控箱高温告警";
CM_ SG_ 2332753777 PowerSWState_49 "单柜开关状态（门把手上的钥匙开关）";
CM_ SG_ 2332753777 FaultClearCommand_49 "故障清除指令";
CM_ SG_ 2332753778 FireFault_Level1_50 "一级消防故障";
CM_ SG_ 2332753778 FireFault_Level2_50 "二级消防故障";
CM_ SG_ 2332753778 TempState_50 "温感状态";
CM_ SG_ 2332753778 FogState_50 "烟感状态";
CM_ SG_ 2332753778 AerosolState_50 "气溶胶状态";
CM_ SG_ 2332753778 AerosolFaultState_50 "气溶胶故障状态";
CM_ SG_ 2332753778 DoorState_50 "门禁状态";
CM_ SG_ 2332753778 ControlBoxFanState_50 "主控箱风机状态";
CM_ SG_ 2332753778 ControlBoxTempHighWarning_50 "主控箱高温告警";
CM_ SG_ 2332753778 PowerSWState_50 "单柜开关状态（门把手上的钥匙开关）";
CM_ SG_ 2332753778 FaultClearCommand_50 "故障清除指令";
CM_ SG_ 2332753779 FireFault_Level1_51 "一级消防故障";
CM_ SG_ 2332753779 FireFault_Level2_51 "二级消防故障";
CM_ SG_ 2332753779 TempState_51 "温感状态";
CM_ SG_ 2332753779 FogState_51 "烟感状态";
CM_ SG_ 2332753779 AerosolState_51 "气溶胶状态";
CM_ SG_ 2332753779 AerosolFaultState_51 "气溶胶故障状态";
CM_ SG_ 2332753779 DoorState_51 "门禁状态";
CM_ SG_ 2332753779 ControlBoxFanState_51 "主控箱风机状态";
CM_ SG_ 2332753779 ControlBoxTempHighWarning_51 "主控箱高温告警";
CM_ SG_ 2332753779 PowerSWState_51 "单柜开关状态（门把手上的钥匙开关）";
CM_ SG_ 2332753779 FaultClearCommand_51 "故障清除指令";
CM_ SG_ 2332753780 FireFault_Level1_52 "一级消防故障";
CM_ SG_ 2332753780 FireFault_Level2_52 "二级消防故障";
CM_ SG_ 2332753780 TempState_52 "温感状态";
CM_ SG_ 2332753780 FogState_52 "烟感状态";
CM_ SG_ 2332753780 AerosolState_52 "气溶胶状态";
CM_ SG_ 2332753780 AerosolFaultState_52 "气溶胶故障状态";
CM_ SG_ 2332753780 DoorState_52 "门禁状态";
CM_ SG_ 2332753780 ControlBoxFanState_52 "主控箱风机状态";
CM_ SG_ 2332753780 ControlBoxTempHighWarning_52 "主控箱高温告警";
CM_ SG_ 2332753780 PowerSWState_52 "单柜开关状态（门把手上的钥匙开关）";
CM_ SG_ 2332753780 FaultClearCommand_52 "故障清除指令";
CM_ SG_ 2332753781 FireFault_Level1_53 "一级消防故障";
CM_ SG_ 2332753781 FireFault_Level2_53 "二级消防故障";
CM_ SG_ 2332753781 TempState_53 "温感状态";
CM_ SG_ 2332753781 FogState_53 "烟感状态";
CM_ SG_ 2332753781 AerosolState_53 "气溶胶状态";
CM_ SG_ 2332753781 AerosolFaultState_53 "气溶胶故障状态";
CM_ SG_ 2332753781 DoorState_53 "门禁状态";
CM_ SG_ 2332753781 ControlBoxFanState_53 "主控箱风机状态";
CM_ SG_ 2332753781 ControlBoxTempHighWarning_53 "主控箱高温告警";
CM_ SG_ 2332753781 PowerSWState_53 "单柜开关状态（门把手上的钥匙开关）";
CM_ SG_ 2332753781 FaultClearCommand_53 "故障清除指令";
CM_ SG_ 2332753782 FireFault_Level1_54 "一级消防故障";
CM_ SG_ 2332753782 FireFault_Level2_54 "二级消防故障";
CM_ SG_ 2332753782 TempState_54 "温感状态";
CM_ SG_ 2332753782 FogState_54 "烟感状态";
CM_ SG_ 2332753782 AerosolState_54 "气溶胶状态";
CM_ SG_ 2332753782 AerosolFaultState_54 "气溶胶故障状态";
CM_ SG_ 2332753782 DoorState_54 "门禁状态";
CM_ SG_ 2332753782 ControlBoxFanState_54 "主控箱风机状态";
CM_ SG_ 2332753782 ControlBoxTempHighWarning_54 "主控箱高温告警";
CM_ SG_ 2332753782 PowerSWState_54 "单柜开关状态（门把手上的钥匙开关）";
CM_ SG_ 2332753782 FaultClearCommand_54 "故障清除指令";
CM_ SG_ 2332753783 FireFault_Level1_55 "一级消防故障";
CM_ SG_ 2332753783 FireFault_Level2_55 "二级消防故障";
CM_ SG_ 2332753783 TempState_55 "温感状态";
CM_ SG_ 2332753783 FogState_55 "烟感状态";
CM_ SG_ 2332753783 AerosolState_55 "气溶胶状态";
CM_ SG_ 2332753783 AerosolFaultState_55 "气溶胶故障状态";
CM_ SG_ 2332753783 DoorState_55 "门禁状态";
CM_ SG_ 2332753783 ControlBoxFanState_55 "主控箱风机状态";
CM_ SG_ 2332753783 ControlBoxTempHighWarning_55 "主控箱高温告警";
CM_ SG_ 2332753783 PowerSWState_55 "单柜开关状态（门把手上的钥匙开关）";
CM_ SG_ 2332753783 FaultClearCommand_55 "故障清除指令";
CM_ SG_ 2332753784 FireFault_Level1_56 "一级消防故障";
CM_ SG_ 2332753784 FireFault_Level2_56 "二级消防故障";
CM_ SG_ 2332753784 TempState_56 "温感状态";
CM_ SG_ 2332753784 FogState_56 "烟感状态";
CM_ SG_ 2332753784 AerosolState_56 "气溶胶状态";
CM_ SG_ 2332753784 AerosolFaultState_56 "气溶胶故障状态";
CM_ SG_ 2332753784 DoorState_56 "门禁状态";
CM_ SG_ 2332753784 ControlBoxFanState_56 "主控箱风机状态";
CM_ SG_ 2332753784 ControlBoxTempHighWarning_56 "主控箱高温告警";
CM_ SG_ 2332753784 PowerSWState_56 "单柜开关状态（门把手上的钥匙开关）";
CM_ SG_ 2332753784 FaultClearCommand_56 "故障清除指令";
CM_ SG_ 2332753785 FireFault_Level1_57 "一级消防故障";
CM_ SG_ 2332753785 FireFault_Level2_57 "二级消防故障";
CM_ SG_ 2332753785 TempState_57 "温感状态";
CM_ SG_ 2332753785 FogState_57 "烟感状态";
CM_ SG_ 2332753785 AerosolState_57 "气溶胶状态";
CM_ SG_ 2332753785 AerosolFaultState_57 "气溶胶故障状态";
CM_ SG_ 2332753785 DoorState_57 "门禁状态";
CM_ SG_ 2332753785 ControlBoxFanState_57 "主控箱风机状态";
CM_ SG_ 2332753785 ControlBoxTempHighWarning_57 "主控箱高温告警";
CM_ SG_ 2332753785 PowerSWState_57 "单柜开关状态（门把手上的钥匙开关）";
CM_ SG_ 2332753785 FaultClearCommand_57 "故障清除指令";
CM_ SG_ 2332753786 FireFault_Level1_58 "一级消防故障";
CM_ SG_ 2332753786 FireFault_Level2_58 "二级消防故障";
CM_ SG_ 2332753786 TempState_58 "温感状态";
CM_ SG_ 2332753786 FogState_58 "烟感状态";
CM_ SG_ 2332753786 AerosolState_58 "气溶胶状态";
CM_ SG_ 2332753786 AerosolFaultState_58 "气溶胶故障状态";
CM_ SG_ 2332753786 DoorState_58 "门禁状态";
CM_ SG_ 2332753786 ControlBoxFanState_58 "主控箱风机状态";
CM_ SG_ 2332753786 ControlBoxTempHighWarning_58 "主控箱高温告警";
CM_ SG_ 2332753786 PowerSWState_58 "单柜开关状态（门把手上的钥匙开关）";
CM_ SG_ 2332753786 FaultClearCommand_58 "故障清除指令";
CM_ SG_ 2332753787 FireFault_Level1_59 "一级消防故障";
CM_ SG_ 2332753787 FireFault_Level2_59 "二级消防故障";
CM_ SG_ 2332753787 TempState_59 "温感状态";
CM_ SG_ 2332753787 FogState_59 "烟感状态";
CM_ SG_ 2332753787 AerosolState_59 "气溶胶状态";
CM_ SG_ 2332753787 AerosolFaultState_59 "气溶胶故障状态";
CM_ SG_ 2332753787 DoorState_59 "门禁状态";
CM_ SG_ 2332753787 ControlBoxFanState_59 "主控箱风机状态";
CM_ SG_ 2332753787 ControlBoxTempHighWarning_59 "主控箱高温告警";
CM_ SG_ 2332753787 PowerSWState_59 "单柜开关状态（门把手上的钥匙开关）";
CM_ SG_ 2332753787 FaultClearCommand_59 "故障清除指令";
CM_ SG_ 2332753788 FireFault_Level1_60 "一级消防故障";
CM_ SG_ 2332753788 FireFault_Level2_60 "二级消防故障";
CM_ SG_ 2332753788 TempState_60 "温感状态";
CM_ SG_ 2332753788 FogState_60 "烟感状态";
CM_ SG_ 2332753788 AerosolState_60 "气溶胶状态";
CM_ SG_ 2332753788 AerosolFaultState_60 "气溶胶故障状态";
CM_ SG_ 2332753788 DoorState_60 "门禁状态";
CM_ SG_ 2332753788 ControlBoxFanState_60 "主控箱风机状态";
CM_ SG_ 2332753788 ControlBoxTempHighWarning_60 "主控箱高温告警";
CM_ SG_ 2332753788 PowerSWState_60 "单柜开关状态（门把手上的钥匙开关）";
CM_ SG_ 2332753788 FaultClearCommand_60 "故障清除指令";
CM_ SG_ 2332753789 FireFault_Level1_61 "一级消防故障";
CM_ SG_ 2332753789 FireFault_Level2_61 "二级消防故障";
CM_ SG_ 2332753789 TempState_61 "温感状态";
CM_ SG_ 2332753789 FogState_61 "烟感状态";
CM_ SG_ 2332753789 AerosolState_61 "气溶胶状态";
CM_ SG_ 2332753789 AerosolFaultState_61 "气溶胶故障状态";
CM_ SG_ 2332753789 DoorState_61 "门禁状态";
CM_ SG_ 2332753789 ControlBoxFanState_61 "主控箱风机状态";
CM_ SG_ 2332753789 ControlBoxTempHighWarning_61 "主控箱高温告警";
CM_ SG_ 2332753789 PowerSWState_61 "单柜开关状态（门把手上的钥匙开关）";
CM_ SG_ 2332753789 FaultClearCommand_61 "故障清除指令";
CM_ SG_ 2332753790 FireFault_Level1_62 "一级消防故障";
CM_ SG_ 2332753790 FireFault_Level2_62 "二级消防故障";
CM_ SG_ 2332753790 TempState_62 "温感状态";
CM_ SG_ 2332753790 FogState_62 "烟感状态";
CM_ SG_ 2332753790 AerosolState_62 "气溶胶状态";
CM_ SG_ 2332753790 AerosolFaultState_62 "气溶胶故障状态";
CM_ SG_ 2332753790 DoorState_62 "门禁状态";
CM_ SG_ 2332753790 ControlBoxFanState_62 "主控箱风机状态";
CM_ SG_ 2332753790 ControlBoxTempHighWarning_62 "主控箱高温告警";
CM_ SG_ 2332753790 PowerSWState_62 "单柜开关状态（门把手上的钥匙开关）";
CM_ SG_ 2332753790 FaultClearCommand_62 "故障清除指令";
CM_ SG_ 2332753791 FireFault_Level1_63 "一级消防故障";
CM_ SG_ 2332753791 FireFault_Level2_63 "二级消防故障";
CM_ SG_ 2332753791 TempState_63 "温感状态";
CM_ SG_ 2332753791 FogState_63 "烟感状态";
CM_ SG_ 2332753791 AerosolState_63 "气溶胶状态";
CM_ SG_ 2332753791 AerosolFaultState_63 "气溶胶故障状态";
CM_ SG_ 2332753791 DoorState_63 "门禁状态";
CM_ SG_ 2332753791 ControlBoxFanState_63 "主控箱风机状态";
CM_ SG_ 2332753791 ControlBoxTempHighWarning_63 "主控箱高温告警";
CM_ SG_ 2332753791 PowerSWState_63 "单柜开关状态（门把手上的钥匙开关）";
CM_ SG_ 2332753791 FaultClearCommand_63 "故障清除指令";
CM_ SG_ 2467491393 S2P_Index_ST_01 "SBMU发送给PC的编码故障码  ";
CM_ SG_ 2467491393 S2P_Index_Err_01 "SBMU发送给PC的编码错误的CSC号";
CM_ SG_ 2467491394 S2P_Index_ST_02 "SBMU发送给PC的编码故障码  ";
CM_ SG_ 2467491394 S2P_Index_Err_02 "SBMU发送给PC的编码错误的CSC号";
CM_ SG_ 2467491395 S2P_Index_ST_03 "SBMU发送给PC的编码故障码  ";
CM_ SG_ 2467491395 S2P_Index_Err_03 "SBMU发送给PC的编码错误的CSC号";
CM_ SG_ 2467491396 S2P_Index_ST_04 "SBMU发送给PC的编码故障码  ";
CM_ SG_ 2467491396 S2P_Index_Err_04 "SBMU发送给PC的编码错误的CSC号";
CM_ SG_ 2467491397 S2P_Index_ST_05 "SBMU发送给PC的编码故障码  ";
CM_ SG_ 2467491397 S2P_Index_Err_05 "SBMU发送给PC的编码错误的CSC号";
CM_ SG_ 2467491398 S2P_Index_ST_06 "SBMU发送给PC的编码故障码  ";
CM_ SG_ 2467491398 S2P_Index_Err_06 "SBMU发送给PC的编码错误的CSC号";
CM_ SG_ 2467491399 S2P_Index_ST_07 "SBMU发送给PC的编码故障码  ";
CM_ SG_ 2467491399 S2P_Index_Err_07 "SBMU发送给PC的编码错误的CSC号";
CM_ SG_ 2467491400 S2P_Index_ST_08 "SBMU发送给PC的编码故障码  ";
CM_ SG_ 2467491400 S2P_Index_Err_08 "SBMU发送给PC的编码错误的CSC号";
CM_ SG_ 2467491401 S2P_Index_ST_09 "SBMU发送给PC的编码故障码  ";
CM_ SG_ 2467491401 S2P_Index_Err_09 "SBMU发送给PC的编码错误的CSC号";
CM_ SG_ 2467491402 S2P_Index_ST_10 "SBMU发送给PC的编码故障码  ";
CM_ SG_ 2467491402 S2P_Index_Err_10 "SBMU发送给PC的编码错误的CSC号";
CM_ SG_ 2467491403 S2P_Index_ST_11 "SBMU发送给PC的编码故障码  ";
CM_ SG_ 2467491403 S2P_Index_Err_11 "SBMU发送给PC的编码错误的CSC号";
CM_ SG_ 2467491404 S2P_Index_ST_12 "SBMU发送给PC的编码故障码  ";
CM_ SG_ 2467491404 S2P_Index_Err_12 "SBMU发送给PC的编码错误的CSC号";
CM_ SG_ 2467491405 S2P_Index_ST_13 "SBMU发送给PC的编码故障码  ";
CM_ SG_ 2467491405 S2P_Index_Err_13 "SBMU发送给PC的编码错误的CSC号";
CM_ SG_ 2467491406 S2P_Index_ST_14 "SBMU发送给PC的编码故障码  ";
CM_ SG_ 2467491406 S2P_Index_Err_14 "SBMU发送给PC的编码错误的CSC号";
CM_ SG_ 2467491407 S2P_Index_ST_15 "SBMU发送给PC的编码故障码  ";
CM_ SG_ 2467491407 S2P_Index_Err_15 "SBMU发送给PC的编码错误的CSC号";
CM_ SG_ 2467491408 S2P_Index_ST_16 "SBMU发送给PC的编码故障码  ";
CM_ SG_ 2467491408 S2P_Index_Err_16 "SBMU发送给PC的编码错误的CSC号";
CM_ SG_ 2467491409 S2P_Index_ST_17 "SBMU发送给PC的编码故障码  ";
CM_ SG_ 2467491409 S2P_Index_Err_17 "SBMU发送给PC的编码错误的CSC号";
CM_ SG_ 2467491410 S2P_Index_ST_18 "SBMU发送给PC的编码故障码  ";
CM_ SG_ 2467491410 S2P_Index_Err_18 "SBMU发送给PC的编码错误的CSC号";
CM_ SG_ 2467491411 S2P_Index_ST_19 "SBMU发送给PC的编码故障码  ";
CM_ SG_ 2467491411 S2P_Index_Err_19 "SBMU发送给PC的编码错误的CSC号";
CM_ SG_ 2467491412 S2P_Index_ST_20 "SBMU发送给PC的编码故障码  ";
CM_ SG_ 2467491412 S2P_Index_Err_20 "SBMU发送给PC的编码错误的CSC号";
CM_ SG_ 2467491413 S2P_Index_ST_21 "SBMU发送给PC的编码故障码  ";
CM_ SG_ 2467491413 S2P_Index_Err_21 "SBMU发送给PC的编码错误的CSC号";
CM_ SG_ 2467491414 S2P_Index_ST_22 "SBMU发送给PC的编码故障码  ";
CM_ SG_ 2467491414 S2P_Index_Err_22 "SBMU发送给PC的编码错误的CSC号";
CM_ SG_ 2467491415 S2P_Index_ST_23 "SBMU发送给PC的编码故障码  ";
CM_ SG_ 2467491415 S2P_Index_Err_23 "SBMU发送给PC的编码错误的CSC号";
CM_ SG_ 2467491416 S2P_Index_ST_24 "SBMU发送给PC的编码故障码  ";
CM_ SG_ 2467491416 S2P_Index_Err_24 "SBMU发送给PC的编码错误的CSC号";
CM_ SG_ 2467491417 S2P_Index_ST_25 "SBMU发送给PC的编码故障码  ";
CM_ SG_ 2467491417 S2P_Index_Err_25 "SBMU发送给PC的编码错误的CSC号";
CM_ SG_ 2467491418 S2P_Index_ST_26 "SBMU发送给PC的编码故障码  ";
CM_ SG_ 2467491418 S2P_Index_Err_26 "SBMU发送给PC的编码错误的CSC号";
CM_ SG_ 2467491419 S2P_Index_ST_27 "SBMU发送给PC的编码故障码  ";
CM_ SG_ 2467491419 S2P_Index_Err_27 "SBMU发送给PC的编码错误的CSC号";
CM_ SG_ 2467491420 S2P_Index_ST_28 "SBMU发送给PC的编码故障码  ";
CM_ SG_ 2467491420 S2P_Index_Err_28 "SBMU发送给PC的编码错误的CSC号";
CM_ SG_ 2467491421 S2P_Index_ST_29 "SBMU发送给PC的编码故障码  ";
CM_ SG_ 2467491421 S2P_Index_Err_29 "SBMU发送给PC的编码错误的CSC号";
CM_ SG_ 2467491422 S2P_Index_ST_30 "SBMU发送给PC的编码故障码  ";
CM_ SG_ 2467491422 S2P_Index_Err_30 "SBMU发送给PC的编码错误的CSC号";
CM_ SG_ 2467491423 S2P_Index_ST_31 "SBMU发送给PC的编码故障码  ";
CM_ SG_ 2467491423 S2P_Index_Err_31 "SBMU发送给PC的编码错误的CSC号";
CM_ SG_ 2467491424 S2P_Index_ST_32 "SBMU发送给PC的编码故障码  ";
CM_ SG_ 2467491424 S2P_Index_Err_32 "SBMU发送给PC的编码错误的CSC号";
CM_ SG_ 2467491425 S2P_Index_ST_33 "SBMU发送给PC的编码故障码  ";
CM_ SG_ 2467491425 S2P_Index_Err_33 "SBMU发送给PC的编码错误的CSC号";
CM_ SG_ 2467491426 S2P_Index_ST_34 "SBMU发送给PC的编码故障码  ";
CM_ SG_ 2467491426 S2P_Index_Err_34 "SBMU发送给PC的编码错误的CSC号";
CM_ SG_ 2467491427 S2P_Index_ST_35 "SBMU发送给PC的编码故障码  ";
CM_ SG_ 2467491427 S2P_Index_Err_35 "SBMU发送给PC的编码错误的CSC号";
CM_ SG_ 2467491428 S2P_Index_ST_36 "SBMU发送给PC的编码故障码  ";
CM_ SG_ 2467491428 S2P_Index_Err_36 "SBMU发送给PC的编码错误的CSC号";
CM_ SG_ 2467491429 S2P_Index_ST_37 "SBMU发送给PC的编码故障码  ";
CM_ SG_ 2467491429 S2P_Index_Err_37 "SBMU发送给PC的编码错误的CSC号";
CM_ SG_ 2467491430 S2P_Index_ST_38 "SBMU发送给PC的编码故障码  ";
CM_ SG_ 2467491430 S2P_Index_Err_38 "SBMU发送给PC的编码错误的CSC号";
CM_ SG_ 2467491431 S2P_Index_ST_39 "SBMU发送给PC的编码故障码  ";
CM_ SG_ 2467491431 S2P_Index_Err_39 "SBMU发送给PC的编码错误的CSC号";
CM_ SG_ 2467491432 S2P_Index_ST_40 "SBMU发送给PC的编码故障码  ";
CM_ SG_ 2467491432 S2P_Index_Err_40 "SBMU发送给PC的编码错误的CSC号";
CM_ SG_ 2467491433 S2P_Index_ST_41 "SBMU发送给PC的编码故障码  ";
CM_ SG_ 2467491433 S2P_Index_Err_41 "SBMU发送给PC的编码错误的CSC号";
CM_ SG_ 2467491434 S2P_Index_ST_42 "SBMU发送给PC的编码故障码  ";
CM_ SG_ 2467491434 S2P_Index_Err_42 "SBMU发送给PC的编码错误的CSC号";
CM_ SG_ 2467491435 S2P_Index_ST_43 "SBMU发送给PC的编码故障码  ";
CM_ SG_ 2467491435 S2P_Index_Err_43 "SBMU发送给PC的编码错误的CSC号";
CM_ SG_ 2467491436 S2P_Index_ST_44 "SBMU发送给PC的编码故障码  ";
CM_ SG_ 2467491436 S2P_Index_Err_44 "SBMU发送给PC的编码错误的CSC号";
CM_ SG_ 2467491437 S2P_Index_ST_45 "SBMU发送给PC的编码故障码  ";
CM_ SG_ 2467491437 S2P_Index_Err_45 "SBMU发送给PC的编码错误的CSC号";
CM_ SG_ 2467491438 S2P_Index_ST_46 "SBMU发送给PC的编码故障码  ";
CM_ SG_ 2467491438 S2P_Index_Err_46 "SBMU发送给PC的编码错误的CSC号";
CM_ SG_ 2467491439 S2P_Index_ST_47 "SBMU发送给PC的编码故障码  ";
CM_ SG_ 2467491439 S2P_Index_Err_47 "SBMU发送给PC的编码错误的CSC号";
CM_ SG_ 2467491440 S2P_Index_ST_48 "SBMU发送给PC的编码故障码  ";
CM_ SG_ 2467491440 S2P_Index_Err_48 "SBMU发送给PC的编码错误的CSC号";
CM_ SG_ 2467491441 S2P_Index_ST_49 "SBMU发送给PC的编码故障码  ";
CM_ SG_ 2467491441 S2P_Index_Err_49 "SBMU发送给PC的编码错误的CSC号";
CM_ SG_ 2467491442 S2P_Index_ST_50 "SBMU发送给PC的编码故障码  ";
CM_ SG_ 2467491442 S2P_Index_Err_50 "SBMU发送给PC的编码错误的CSC号";
CM_ SG_ 2467491443 S2P_Index_ST_51 "SBMU发送给PC的编码故障码  ";
CM_ SG_ 2467491443 S2P_Index_Err_51 "SBMU发送给PC的编码错误的CSC号";
CM_ SG_ 2467491444 S2P_Index_ST_52 "SBMU发送给PC的编码故障码  ";
CM_ SG_ 2467491444 S2P_Index_Err_52 "SBMU发送给PC的编码错误的CSC号";
CM_ SG_ 2467491445 S2P_Index_ST_53 "SBMU发送给PC的编码故障码  ";
CM_ SG_ 2467491445 S2P_Index_Err_53 "SBMU发送给PC的编码错误的CSC号";
CM_ SG_ 2467491446 S2P_Index_ST_54 "SBMU发送给PC的编码故障码  ";
CM_ SG_ 2467491446 S2P_Index_Err_54 "SBMU发送给PC的编码错误的CSC号";
CM_ SG_ 2467491447 S2P_Index_ST_55 "SBMU发送给PC的编码故障码  ";
CM_ SG_ 2467491447 S2P_Index_Err_55 "SBMU发送给PC的编码错误的CSC号";
CM_ SG_ 2467491448 S2P_Index_ST_56 "SBMU发送给PC的编码故障码  ";
CM_ SG_ 2467491448 S2P_Index_Err_56 "SBMU发送给PC的编码错误的CSC号";
CM_ SG_ 2467491449 S2P_Index_ST_57 "SBMU发送给PC的编码故障码  ";
CM_ SG_ 2467491449 S2P_Index_Err_57 "SBMU发送给PC的编码错误的CSC号";
CM_ SG_ 2467491450 S2P_Index_ST_58 "SBMU发送给PC的编码故障码  ";
CM_ SG_ 2467491450 S2P_Index_Err_58 "SBMU发送给PC的编码错误的CSC号";
CM_ SG_ 2467491451 S2P_Index_ST_59 "SBMU发送给PC的编码故障码  ";
CM_ SG_ 2467491451 S2P_Index_Err_59 "SBMU发送给PC的编码错误的CSC号";
CM_ SG_ 2467491452 S2P_Index_ST_60 "SBMU发送给PC的编码故障码  ";
CM_ SG_ 2467491452 S2P_Index_Err_60 "SBMU发送给PC的编码错误的CSC号";
CM_ SG_ 2467491453 S2P_Index_ST_61 "SBMU发送给PC的编码故障码  ";
CM_ SG_ 2467491453 S2P_Index_Err_61 "SBMU发送给PC的编码错误的CSC号";
CM_ SG_ 2467491454 S2P_Index_ST_62 "SBMU发送给PC的编码故障码  ";
CM_ SG_ 2467491454 S2P_Index_Err_62 "SBMU发送给PC的编码错误的CSC号";
CM_ SG_ 2467491455 S2P_Index_ST_63 "SBMU发送给PC的编码故障码  ";
CM_ SG_ 2467491455 S2P_Index_Err_63 "SBMU发送给PC的编码错误的CSC号";
CM_ SG_ 2400316993 CSC_U_No_01 "CSC号";
CM_ SG_ 2400316993 CSC_Ucell_Frame_Index_01 "当前CSC中单体电压数据帧序号";
CM_ SG_ 2400316993 CSC_Ucell_01_01 "01 电池单体电压";
CM_ SG_ 2400316993 CSC_Ucell_02_01 "02 电池单体电压";
CM_ SG_ 2400316993 CSC_Ucell_03_01 "03电池单体电压";
CM_ SG_ 2400316993 CSC_Ucell_04_01 "04  电池单体电压";
CM_ SG_ 2400316993 CSC_Ucell_05_01 "05 电池单体电压";
CM_ SG_ 2400316993 CSC_Ucell_06_01 "06 电池单体电压";
CM_ SG_ 2400316993 CSC_Ucell_07_01 "07  电池单体电压";
CM_ SG_ 2400316993 CSC_Ucell_08_01 "08 电池单体电压";
CM_ SG_ 2400316993 CSC_Ucell_09_01 "09 电池单体电压";
CM_ SG_ 2400316993 CSC_Ucell_10_01 "10 电池单体电压";
CM_ SG_ 2400316993 CSC_Ucell_11_01 "11电池单体电压";
CM_ SG_ 2400316993 CSC_Ucell_12_01 "12 电池单体电压";
CM_ SG_ 2400316993 CSC_Ucell_13_01 "13  电池单体电压";
CM_ SG_ 2400316993 CSC_Ucell_14_01 "14  电池单体电压";
CM_ SG_ 2400316993 CSC_Ucell_15_01 "15 电池单体电压";
CM_ SG_ 2400316993 CSC_Ucell_16_01 "16 电池单体电压";
CM_ SG_ 2400316993 CSC_Ucell_17_01 "17 电池单体电压";
CM_ SG_ 2400316993 CSC_Ucell_18_01 "18 电池单体电压";
CM_ SG_ 2400316993 CSC_Ucell_19_01 "19  电池单体电压";
CM_ SG_ 2400316993 CSC_Ucell_20_01 "20  电池单体电压";
CM_ SG_ 2400316993 CSC_Ucell_21_01 "21 电池单体电压";
CM_ SG_ 2400316993 CSC_Ucell_22_01 "22 电池单体电压";
CM_ SG_ 2400316993 CSC_Ucell_23_01 "23 电池单体电压";
CM_ SG_ 2400316993 CSC_Ucell_24_01 "24 电池单体电压";
CM_ SG_ 2400316993 CSC_Ucell_25_01 "25 电池单体电压";
CM_ SG_ 2400316993 CSC_Ucell_26_01 "26 电池单体电压";
CM_ SG_ 2400316993 CSC_Ucell_27_01 "27 电池单体电压";
CM_ SG_ 2400316993 CSC_Ucell_28_01 "28 电池单体电压";
CM_ SG_ 2400316993 CSC_Ucell_29_01 "29 电池单体电压";
CM_ SG_ 2400316993 CSC_Ucell_30_01 "30 电池单体电压";
CM_ SG_ 2400316993 CSC_Ucell_31_01 "31 电池单体电压";
CM_ SG_ 2400316993 CSC_Ucell_32_01 "32 电池单体电压";
CM_ SG_ 2400316993 CSC_Ucell_33_01 "33 电池单体电压";
CM_ SG_ 2400316993 CSC_Ucell_34_01 "34 电池单体电压";
CM_ SG_ 2400316993 CSC_Ucell_35_01 "35 电池单体电压";
CM_ SG_ 2400316993 CSC_Ucell_36_01 "36 电池单体电压";
CM_ SG_ 2400316993 CSC_Ucell_37_01 "37 电池单体电压";
CM_ SG_ 2400316993 CSC_Ucell_38_01 "38 电池单体电压";
CM_ SG_ 2400316993 CSC_Ucell_39_01 "39 电池单体电压";
CM_ SG_ 2400316993 CSC_Ucell_40_01 "40 电池单体电压";
CM_ SG_ 2400316993 CSC_Ucell_41_01 "41 电池单体电压";
CM_ SG_ 2400316993 CSC_Ucell_42_01 "42 电池单体电压";
CM_ SG_ 2400316993 CSC_Ucell_43_01 "43 电池单体电压";
CM_ SG_ 2400316993 CSC_Ucell_44_01 "44 电池单体电压";
CM_ SG_ 2400316993 CSC_Ucell_45_01 "45 电池单体电压";
CM_ SG_ 2400316993 CSC_Ucell_46_01 "46 电池单体电压";
CM_ SG_ 2400316993 CSC_Ucell_47_01 "47 电池单体电压";
CM_ SG_ 2400316993 CSC_Ucell_48_01 "48 电池单体电压";
CM_ SG_ 2400316993 CSC_Ucell_49_01 "49 电池单体电压";
CM_ SG_ 2400316993 CSC_Ucell_50_01 "50 电池单体电压";
CM_ SG_ 2400316993 CSC_Ucell_51_01 "51 电池单体电压";
CM_ SG_ 2400316993 CSC_Ucell_52_01 "52 电池单体电压";
CM_ SG_ 2400316993 CSC_Ucell_53_01 "53 电池单体电压";
CM_ SG_ 2400316993 CSC_Ucell_54_01 "54 电池单体电压";
CM_ SG_ 2400316993 CSC_Ucell_55_01 "55 电池单体电压";
CM_ SG_ 2400316993 CSC_Ucell_56_01 "56 电池单体电压";
CM_ SG_ 2400316993 CSC_Ucell_57_01 "57 电池单体电压";
CM_ SG_ 2400316994 CSC_U_No_02 "CSC号";
CM_ SG_ 2400316994 CSC_Ucell_Frame_Index_02 "当前CSC中单体电压数据帧序号";
CM_ SG_ 2400316994 CSC_Ucell_01_02 "01 电池单体电压";
CM_ SG_ 2400316994 CSC_Ucell_02_02 "02 电池单体电压";
CM_ SG_ 2400316994 CSC_Ucell_03_02 "03电池单体电压";
CM_ SG_ 2400316994 CSC_Ucell_04_02 "04  电池单体电压";
CM_ SG_ 2400316994 CSC_Ucell_05_02 "05 电池单体电压";
CM_ SG_ 2400316994 CSC_Ucell_06_02 "06 电池单体电压";
CM_ SG_ 2400316994 CSC_Ucell_07_02 "07  电池单体电压";
CM_ SG_ 2400316994 CSC_Ucell_08_02 "08 电池单体电压";
CM_ SG_ 2400316994 CSC_Ucell_09_02 "09 电池单体电压";
CM_ SG_ 2400316994 CSC_Ucell_10_02 "10 电池单体电压";
CM_ SG_ 2400316994 CSC_Ucell_11_02 "11电池单体电压";
CM_ SG_ 2400316994 CSC_Ucell_12_02 "12 电池单体电压";
CM_ SG_ 2400316994 CSC_Ucell_13_02 "13  电池单体电压";
CM_ SG_ 2400316994 CSC_Ucell_14_02 "14  电池单体电压";
CM_ SG_ 2400316994 CSC_Ucell_15_02 "15 电池单体电压";
CM_ SG_ 2400316994 CSC_Ucell_16_02 "16 电池单体电压";
CM_ SG_ 2400316994 CSC_Ucell_17_02 "17 电池单体电压";
CM_ SG_ 2400316994 CSC_Ucell_18_02 "18 电池单体电压";
CM_ SG_ 2400316994 CSC_Ucell_19_02 "19  电池单体电压";
CM_ SG_ 2400316994 CSC_Ucell_20_02 "20  电池单体电压";
CM_ SG_ 2400316994 CSC_Ucell_21_02 "21 电池单体电压";
CM_ SG_ 2400316994 CSC_Ucell_22_02 "22 电池单体电压";
CM_ SG_ 2400316994 CSC_Ucell_23_02 "23 电池单体电压";
CM_ SG_ 2400316994 CSC_Ucell_24_02 "24 电池单体电压";
CM_ SG_ 2400316994 CSC_Ucell_25_02 "25 电池单体电压";
CM_ SG_ 2400316994 CSC_Ucell_26_02 "26 电池单体电压";
CM_ SG_ 2400316994 CSC_Ucell_27_02 "27 电池单体电压";
CM_ SG_ 2400316994 CSC_Ucell_28_02 "28 电池单体电压";
CM_ SG_ 2400316994 CSC_Ucell_29_02 "29 电池单体电压";
CM_ SG_ 2400316994 CSC_Ucell_30_02 "30 电池单体电压";
CM_ SG_ 2400316994 CSC_Ucell_31_02 "31 电池单体电压";
CM_ SG_ 2400316994 CSC_Ucell_32_02 "32 电池单体电压";
CM_ SG_ 2400316994 CSC_Ucell_33_02 "33 电池单体电压";
CM_ SG_ 2400316994 CSC_Ucell_34_02 "34 电池单体电压";
CM_ SG_ 2400316994 CSC_Ucell_35_02 "35 电池单体电压";
CM_ SG_ 2400316994 CSC_Ucell_36_02 "36 电池单体电压";
CM_ SG_ 2400316994 CSC_Ucell_37_02 "37 电池单体电压";
CM_ SG_ 2400316994 CSC_Ucell_38_02 "38 电池单体电压";
CM_ SG_ 2400316994 CSC_Ucell_39_02 "39 电池单体电压";
CM_ SG_ 2400316994 CSC_Ucell_40_02 "40 电池单体电压";
CM_ SG_ 2400316994 CSC_Ucell_41_02 "41 电池单体电压";
CM_ SG_ 2400316994 CSC_Ucell_42_02 "42 电池单体电压";
CM_ SG_ 2400316994 CSC_Ucell_43_02 "43 电池单体电压";
CM_ SG_ 2400316994 CSC_Ucell_44_02 "44 电池单体电压";
CM_ SG_ 2400316994 CSC_Ucell_45_02 "45 电池单体电压";
CM_ SG_ 2400316994 CSC_Ucell_46_02 "46 电池单体电压";
CM_ SG_ 2400316994 CSC_Ucell_47_02 "47 电池单体电压";
CM_ SG_ 2400316994 CSC_Ucell_48_02 "48 电池单体电压";
CM_ SG_ 2400316994 CSC_Ucell_49_02 "49 电池单体电压";
CM_ SG_ 2400316994 CSC_Ucell_50_02 "50 电池单体电压";
CM_ SG_ 2400316994 CSC_Ucell_51_02 "51 电池单体电压";
CM_ SG_ 2400316994 CSC_Ucell_52_02 "52 电池单体电压";
CM_ SG_ 2400316994 CSC_Ucell_53_02 "53 电池单体电压";
CM_ SG_ 2400316994 CSC_Ucell_54_02 "54 电池单体电压";
CM_ SG_ 2400316994 CSC_Ucell_55_02 "55 电池单体电压";
CM_ SG_ 2400316994 CSC_Ucell_56_02 "56 电池单体电压";
CM_ SG_ 2400316994 CSC_Ucell_57_02 "57 电池单体电压";
CM_ SG_ 2400316995 CSC_U_No_03 "CSC号";
CM_ SG_ 2400316995 CSC_Ucell_Frame_Index_03 "当前CSC中单体电压数据帧序号";
CM_ SG_ 2400316995 CSC_Ucell_01_03 "01 电池单体电压";
CM_ SG_ 2400316995 CSC_Ucell_02_03 "02 电池单体电压";
CM_ SG_ 2400316995 CSC_Ucell_03_03 "03电池单体电压";
CM_ SG_ 2400316995 CSC_Ucell_04_03 "04  电池单体电压";
CM_ SG_ 2400316995 CSC_Ucell_05_03 "05 电池单体电压";
CM_ SG_ 2400316995 CSC_Ucell_06_03 "06 电池单体电压";
CM_ SG_ 2400316995 CSC_Ucell_07_03 "07  电池单体电压";
CM_ SG_ 2400316995 CSC_Ucell_08_03 "08 电池单体电压";
CM_ SG_ 2400316995 CSC_Ucell_09_03 "09 电池单体电压";
CM_ SG_ 2400316995 CSC_Ucell_10_03 "10 电池单体电压";
CM_ SG_ 2400316995 CSC_Ucell_11_03 "11电池单体电压";
CM_ SG_ 2400316995 CSC_Ucell_12_03 "12 电池单体电压";
CM_ SG_ 2400316995 CSC_Ucell_13_03 "13  电池单体电压";
CM_ SG_ 2400316995 CSC_Ucell_14_03 "14  电池单体电压";
CM_ SG_ 2400316995 CSC_Ucell_15_03 "15 电池单体电压";
CM_ SG_ 2400316995 CSC_Ucell_16_03 "16 电池单体电压";
CM_ SG_ 2400316995 CSC_Ucell_17_03 "17 电池单体电压";
CM_ SG_ 2400316995 CSC_Ucell_18_03 "18 电池单体电压";
CM_ SG_ 2400316995 CSC_Ucell_19_03 "19  电池单体电压";
CM_ SG_ 2400316995 CSC_Ucell_20_03 "20  电池单体电压";
CM_ SG_ 2400316995 CSC_Ucell_21_03 "21 电池单体电压";
CM_ SG_ 2400316995 CSC_Ucell_22_03 "22 电池单体电压";
CM_ SG_ 2400316995 CSC_Ucell_23_03 "23 电池单体电压";
CM_ SG_ 2400316995 CSC_Ucell_24_03 "24 电池单体电压";
CM_ SG_ 2400316995 CSC_Ucell_25_03 "25 电池单体电压";
CM_ SG_ 2400316995 CSC_Ucell_26_03 "26 电池单体电压";
CM_ SG_ 2400316995 CSC_Ucell_27_03 "27 电池单体电压";
CM_ SG_ 2400316995 CSC_Ucell_28_03 "28 电池单体电压";
CM_ SG_ 2400316995 CSC_Ucell_29_03 "29 电池单体电压";
CM_ SG_ 2400316995 CSC_Ucell_30_03 "30 电池单体电压";
CM_ SG_ 2400316995 CSC_Ucell_31_03 "31 电池单体电压";
CM_ SG_ 2400316995 CSC_Ucell_32_03 "32 电池单体电压";
CM_ SG_ 2400316995 CSC_Ucell_33_03 "33 电池单体电压";
CM_ SG_ 2400316995 CSC_Ucell_34_03 "34 电池单体电压";
CM_ SG_ 2400316995 CSC_Ucell_35_03 "35 电池单体电压";
CM_ SG_ 2400316995 CSC_Ucell_36_03 "36 电池单体电压";
CM_ SG_ 2400316995 CSC_Ucell_37_03 "37 电池单体电压";
CM_ SG_ 2400316995 CSC_Ucell_38_03 "38 电池单体电压";
CM_ SG_ 2400316995 CSC_Ucell_39_03 "39 电池单体电压";
CM_ SG_ 2400316995 CSC_Ucell_40_03 "40 电池单体电压";
CM_ SG_ 2400316995 CSC_Ucell_41_03 "41 电池单体电压";
CM_ SG_ 2400316995 CSC_Ucell_42_03 "42 电池单体电压";
CM_ SG_ 2400316995 CSC_Ucell_43_03 "43 电池单体电压";
CM_ SG_ 2400316995 CSC_Ucell_44_03 "44 电池单体电压";
CM_ SG_ 2400316995 CSC_Ucell_45_03 "45 电池单体电压";
CM_ SG_ 2400316995 CSC_Ucell_46_03 "46 电池单体电压";
CM_ SG_ 2400316995 CSC_Ucell_47_03 "47 电池单体电压";
CM_ SG_ 2400316995 CSC_Ucell_48_03 "48 电池单体电压";
CM_ SG_ 2400316995 CSC_Ucell_49_03 "49 电池单体电压";
CM_ SG_ 2400316995 CSC_Ucell_50_03 "50 电池单体电压";
CM_ SG_ 2400316995 CSC_Ucell_51_03 "51 电池单体电压";
CM_ SG_ 2400316995 CSC_Ucell_52_03 "52 电池单体电压";
CM_ SG_ 2400316995 CSC_Ucell_53_03 "53 电池单体电压";
CM_ SG_ 2400316995 CSC_Ucell_54_03 "54 电池单体电压";
CM_ SG_ 2400316995 CSC_Ucell_55_03 "55 电池单体电压";
CM_ SG_ 2400316995 CSC_Ucell_56_03 "56 电池单体电压";
CM_ SG_ 2400316995 CSC_Ucell_57_03 "57 电池单体电压";
CM_ SG_ 2400316996 CSC_U_No_04 "CSC号";
CM_ SG_ 2400316996 CSC_Ucell_Frame_Index_04 "当前CSC中单体电压数据帧序号";
CM_ SG_ 2400316996 CSC_Ucell_01_04 "01 电池单体电压";
CM_ SG_ 2400316996 CSC_Ucell_02_04 "02 电池单体电压";
CM_ SG_ 2400316996 CSC_Ucell_03_04 "03电池单体电压";
CM_ SG_ 2400316996 CSC_Ucell_04_04 "04  电池单体电压";
CM_ SG_ 2400316996 CSC_Ucell_05_04 "05 电池单体电压";
CM_ SG_ 2400316996 CSC_Ucell_06_04 "06 电池单体电压";
CM_ SG_ 2400316996 CSC_Ucell_07_04 "07  电池单体电压";
CM_ SG_ 2400316996 CSC_Ucell_08_04 "08 电池单体电压";
CM_ SG_ 2400316996 CSC_Ucell_09_04 "09 电池单体电压";
CM_ SG_ 2400316996 CSC_Ucell_10_04 "10 电池单体电压";
CM_ SG_ 2400316996 CSC_Ucell_11_04 "11电池单体电压";
CM_ SG_ 2400316996 CSC_Ucell_12_04 "12 电池单体电压";
CM_ SG_ 2400316996 CSC_Ucell_13_04 "13  电池单体电压";
CM_ SG_ 2400316996 CSC_Ucell_14_04 "14  电池单体电压";
CM_ SG_ 2400316996 CSC_Ucell_15_04 "15 电池单体电压";
CM_ SG_ 2400316996 CSC_Ucell_16_04 "16 电池单体电压";
CM_ SG_ 2400316996 CSC_Ucell_17_04 "17 电池单体电压";
CM_ SG_ 2400316996 CSC_Ucell_18_04 "18 电池单体电压";
CM_ SG_ 2400316996 CSC_Ucell_19_04 "19  电池单体电压";
CM_ SG_ 2400316996 CSC_Ucell_20_04 "20  电池单体电压";
CM_ SG_ 2400316996 CSC_Ucell_21_04 "21 电池单体电压";
CM_ SG_ 2400316996 CSC_Ucell_22_04 "22 电池单体电压";
CM_ SG_ 2400316996 CSC_Ucell_23_04 "23 电池单体电压";
CM_ SG_ 2400316996 CSC_Ucell_24_04 "24 电池单体电压";
CM_ SG_ 2400316996 CSC_Ucell_25_04 "25 电池单体电压";
CM_ SG_ 2400316996 CSC_Ucell_26_04 "26 电池单体电压";
CM_ SG_ 2400316996 CSC_Ucell_27_04 "27 电池单体电压";
CM_ SG_ 2400316996 CSC_Ucell_28_04 "28 电池单体电压";
CM_ SG_ 2400316996 CSC_Ucell_29_04 "29 电池单体电压";
CM_ SG_ 2400316996 CSC_Ucell_30_04 "30 电池单体电压";
CM_ SG_ 2400316996 CSC_Ucell_31_04 "31 电池单体电压";
CM_ SG_ 2400316996 CSC_Ucell_32_04 "32 电池单体电压";
CM_ SG_ 2400316996 CSC_Ucell_33_04 "33 电池单体电压";
CM_ SG_ 2400316996 CSC_Ucell_34_04 "34 电池单体电压";
CM_ SG_ 2400316996 CSC_Ucell_35_04 "35 电池单体电压";
CM_ SG_ 2400316996 CSC_Ucell_36_04 "36 电池单体电压";
CM_ SG_ 2400316996 CSC_Ucell_37_04 "37 电池单体电压";
CM_ SG_ 2400316996 CSC_Ucell_38_04 "38 电池单体电压";
CM_ SG_ 2400316996 CSC_Ucell_39_04 "39 电池单体电压";
CM_ SG_ 2400316996 CSC_Ucell_40_04 "40 电池单体电压";
CM_ SG_ 2400316996 CSC_Ucell_41_04 "41 电池单体电压";
CM_ SG_ 2400316996 CSC_Ucell_42_04 "42 电池单体电压";
CM_ SG_ 2400316996 CSC_Ucell_43_04 "43 电池单体电压";
CM_ SG_ 2400316996 CSC_Ucell_44_04 "44 电池单体电压";
CM_ SG_ 2400316996 CSC_Ucell_45_04 "45 电池单体电压";
CM_ SG_ 2400316996 CSC_Ucell_46_04 "46 电池单体电压";
CM_ SG_ 2400316996 CSC_Ucell_47_04 "47 电池单体电压";
CM_ SG_ 2400316996 CSC_Ucell_48_04 "48 电池单体电压";
CM_ SG_ 2400316996 CSC_Ucell_49_04 "49 电池单体电压";
CM_ SG_ 2400316996 CSC_Ucell_50_04 "50 电池单体电压";
CM_ SG_ 2400316996 CSC_Ucell_51_04 "51 电池单体电压";
CM_ SG_ 2400316996 CSC_Ucell_52_04 "52 电池单体电压";
CM_ SG_ 2400316996 CSC_Ucell_53_04 "53 电池单体电压";
CM_ SG_ 2400316996 CSC_Ucell_54_04 "54 电池单体电压";
CM_ SG_ 2400316996 CSC_Ucell_55_04 "55 电池单体电压";
CM_ SG_ 2400316996 CSC_Ucell_56_04 "56 电池单体电压";
CM_ SG_ 2400316996 CSC_Ucell_57_04 "57 电池单体电压";
CM_ SG_ 2400316997 CSC_U_No_05 "CSC号";
CM_ SG_ 2400316997 CSC_Ucell_Frame_Index_05 "当前CSC中单体电压数据帧序号";
CM_ SG_ 2400316997 CSC_Ucell_01_05 "01 电池单体电压";
CM_ SG_ 2400316997 CSC_Ucell_02_05 "02 电池单体电压";
CM_ SG_ 2400316997 CSC_Ucell_03_05 "03电池单体电压";
CM_ SG_ 2400316997 CSC_Ucell_04_05 "04  电池单体电压";
CM_ SG_ 2400316997 CSC_Ucell_05_05 "05 电池单体电压";
CM_ SG_ 2400316997 CSC_Ucell_06_05 "06 电池单体电压";
CM_ SG_ 2400316997 CSC_Ucell_07_05 "07  电池单体电压";
CM_ SG_ 2400316997 CSC_Ucell_08_05 "08 电池单体电压";
CM_ SG_ 2400316997 CSC_Ucell_09_05 "09 电池单体电压";
CM_ SG_ 2400316997 CSC_Ucell_10_05 "10 电池单体电压";
CM_ SG_ 2400316997 CSC_Ucell_11_05 "11电池单体电压";
CM_ SG_ 2400316997 CSC_Ucell_12_05 "12 电池单体电压";
CM_ SG_ 2400316997 CSC_Ucell_13_05 "13  电池单体电压";
CM_ SG_ 2400316997 CSC_Ucell_14_05 "14  电池单体电压";
CM_ SG_ 2400316997 CSC_Ucell_15_05 "15 电池单体电压";
CM_ SG_ 2400316997 CSC_Ucell_16_05 "16 电池单体电压";
CM_ SG_ 2400316997 CSC_Ucell_17_05 "17 电池单体电压";
CM_ SG_ 2400316997 CSC_Ucell_18_05 "18 电池单体电压";
CM_ SG_ 2400316997 CSC_Ucell_19_05 "19  电池单体电压";
CM_ SG_ 2400316997 CSC_Ucell_20_05 "20  电池单体电压";
CM_ SG_ 2400316997 CSC_Ucell_21_05 "21 电池单体电压";
CM_ SG_ 2400316997 CSC_Ucell_22_05 "22 电池单体电压";
CM_ SG_ 2400316997 CSC_Ucell_23_05 "23 电池单体电压";
CM_ SG_ 2400316997 CSC_Ucell_24_05 "24 电池单体电压";
CM_ SG_ 2400316997 CSC_Ucell_25_05 "25 电池单体电压";
CM_ SG_ 2400316997 CSC_Ucell_26_05 "26 电池单体电压";
CM_ SG_ 2400316997 CSC_Ucell_27_05 "27 电池单体电压";
CM_ SG_ 2400316997 CSC_Ucell_28_05 "28 电池单体电压";
CM_ SG_ 2400316997 CSC_Ucell_29_05 "29 电池单体电压";
CM_ SG_ 2400316997 CSC_Ucell_30_05 "30 电池单体电压";
CM_ SG_ 2400316997 CSC_Ucell_31_05 "31 电池单体电压";
CM_ SG_ 2400316997 CSC_Ucell_32_05 "32 电池单体电压";
CM_ SG_ 2400316997 CSC_Ucell_33_05 "33 电池单体电压";
CM_ SG_ 2400316997 CSC_Ucell_34_05 "34 电池单体电压";
CM_ SG_ 2400316997 CSC_Ucell_35_05 "35 电池单体电压";
CM_ SG_ 2400316997 CSC_Ucell_36_05 "36 电池单体电压";
CM_ SG_ 2400316997 CSC_Ucell_37_05 "37 电池单体电压";
CM_ SG_ 2400316997 CSC_Ucell_38_05 "38 电池单体电压";
CM_ SG_ 2400316997 CSC_Ucell_39_05 "39 电池单体电压";
CM_ SG_ 2400316997 CSC_Ucell_40_05 "40 电池单体电压";
CM_ SG_ 2400316997 CSC_Ucell_41_05 "41 电池单体电压";
CM_ SG_ 2400316997 CSC_Ucell_42_05 "42 电池单体电压";
CM_ SG_ 2400316997 CSC_Ucell_43_05 "43 电池单体电压";
CM_ SG_ 2400316997 CSC_Ucell_44_05 "44 电池单体电压";
CM_ SG_ 2400316997 CSC_Ucell_45_05 "45 电池单体电压";
CM_ SG_ 2400316997 CSC_Ucell_46_05 "46 电池单体电压";
CM_ SG_ 2400316997 CSC_Ucell_47_05 "47 电池单体电压";
CM_ SG_ 2400316997 CSC_Ucell_48_05 "48 电池单体电压";
CM_ SG_ 2400316997 CSC_Ucell_49_05 "49 电池单体电压";
CM_ SG_ 2400316997 CSC_Ucell_50_05 "50 电池单体电压";
CM_ SG_ 2400316997 CSC_Ucell_51_05 "51 电池单体电压";
CM_ SG_ 2400316997 CSC_Ucell_52_05 "52 电池单体电压";
CM_ SG_ 2400316997 CSC_Ucell_53_05 "53 电池单体电压";
CM_ SG_ 2400316997 CSC_Ucell_54_05 "54 电池单体电压";
CM_ SG_ 2400316997 CSC_Ucell_55_05 "55 电池单体电压";
CM_ SG_ 2400316997 CSC_Ucell_56_05 "56 电池单体电压";
CM_ SG_ 2400316997 CSC_Ucell_57_05 "57 电池单体电压";
CM_ SG_ 2400316998 CSC_U_No_06 "CSC号";
CM_ SG_ 2400316998 CSC_Ucell_Frame_Index_06 "当前CSC中单体电压数据帧序号";
CM_ SG_ 2400316998 CSC_Ucell_01_06 "01 电池单体电压";
CM_ SG_ 2400316998 CSC_Ucell_02_06 "02 电池单体电压";
CM_ SG_ 2400316998 CSC_Ucell_03_06 "03电池单体电压";
CM_ SG_ 2400316998 CSC_Ucell_04_06 "04  电池单体电压";
CM_ SG_ 2400316998 CSC_Ucell_05_06 "05 电池单体电压";
CM_ SG_ 2400316998 CSC_Ucell_06_06 "06 电池单体电压";
CM_ SG_ 2400316998 CSC_Ucell_07_06 "07  电池单体电压";
CM_ SG_ 2400316998 CSC_Ucell_08_06 "08 电池单体电压";
CM_ SG_ 2400316998 CSC_Ucell_09_06 "09 电池单体电压";
CM_ SG_ 2400316998 CSC_Ucell_10_06 "10 电池单体电压";
CM_ SG_ 2400316998 CSC_Ucell_11_06 "11电池单体电压";
CM_ SG_ 2400316998 CSC_Ucell_12_06 "12 电池单体电压";
CM_ SG_ 2400316998 CSC_Ucell_13_06 "13  电池单体电压";
CM_ SG_ 2400316998 CSC_Ucell_14_06 "14  电池单体电压";
CM_ SG_ 2400316998 CSC_Ucell_15_06 "15 电池单体电压";
CM_ SG_ 2400316998 CSC_Ucell_16_06 "16 电池单体电压";
CM_ SG_ 2400316998 CSC_Ucell_17_06 "17 电池单体电压";
CM_ SG_ 2400316998 CSC_Ucell_18_06 "18 电池单体电压";
CM_ SG_ 2400316998 CSC_Ucell_19_06 "19  电池单体电压";
CM_ SG_ 2400316998 CSC_Ucell_20_06 "20  电池单体电压";
CM_ SG_ 2400316998 CSC_Ucell_21_06 "21 电池单体电压";
CM_ SG_ 2400316998 CSC_Ucell_22_06 "22 电池单体电压";
CM_ SG_ 2400316998 CSC_Ucell_23_06 "23 电池单体电压";
CM_ SG_ 2400316998 CSC_Ucell_24_06 "24 电池单体电压";
CM_ SG_ 2400316998 CSC_Ucell_25_06 "25 电池单体电压";
CM_ SG_ 2400316998 CSC_Ucell_26_06 "26 电池单体电压";
CM_ SG_ 2400316998 CSC_Ucell_27_06 "27 电池单体电压";
CM_ SG_ 2400316998 CSC_Ucell_28_06 "28 电池单体电压";
CM_ SG_ 2400316998 CSC_Ucell_29_06 "29 电池单体电压";
CM_ SG_ 2400316998 CSC_Ucell_30_06 "30 电池单体电压";
CM_ SG_ 2400316998 CSC_Ucell_31_06 "31 电池单体电压";
CM_ SG_ 2400316998 CSC_Ucell_32_06 "32 电池单体电压";
CM_ SG_ 2400316998 CSC_Ucell_33_06 "33 电池单体电压";
CM_ SG_ 2400316998 CSC_Ucell_34_06 "34 电池单体电压";
CM_ SG_ 2400316998 CSC_Ucell_35_06 "35 电池单体电压";
CM_ SG_ 2400316998 CSC_Ucell_36_06 "36 电池单体电压";
CM_ SG_ 2400316998 CSC_Ucell_37_06 "37 电池单体电压";
CM_ SG_ 2400316998 CSC_Ucell_38_06 "38 电池单体电压";
CM_ SG_ 2400316998 CSC_Ucell_39_06 "39 电池单体电压";
CM_ SG_ 2400316998 CSC_Ucell_40_06 "40 电池单体电压";
CM_ SG_ 2400316998 CSC_Ucell_41_06 "41 电池单体电压";
CM_ SG_ 2400316998 CSC_Ucell_42_06 "42 电池单体电压";
CM_ SG_ 2400316998 CSC_Ucell_43_06 "43 电池单体电压";
CM_ SG_ 2400316998 CSC_Ucell_44_06 "44 电池单体电压";
CM_ SG_ 2400316998 CSC_Ucell_45_06 "45 电池单体电压";
CM_ SG_ 2400316998 CSC_Ucell_46_06 "46 电池单体电压";
CM_ SG_ 2400316998 CSC_Ucell_47_06 "47 电池单体电压";
CM_ SG_ 2400316998 CSC_Ucell_48_06 "48 电池单体电压";
CM_ SG_ 2400316998 CSC_Ucell_49_06 "49 电池单体电压";
CM_ SG_ 2400316998 CSC_Ucell_50_06 "50 电池单体电压";
CM_ SG_ 2400316998 CSC_Ucell_51_06 "51 电池单体电压";
CM_ SG_ 2400316998 CSC_Ucell_52_06 "52 电池单体电压";
CM_ SG_ 2400316998 CSC_Ucell_53_06 "53 电池单体电压";
CM_ SG_ 2400316998 CSC_Ucell_54_06 "54 电池单体电压";
CM_ SG_ 2400316998 CSC_Ucell_55_06 "55 电池单体电压";
CM_ SG_ 2400316998 CSC_Ucell_56_06 "56 电池单体电压";
CM_ SG_ 2400316998 CSC_Ucell_57_06 "57 电池单体电压";
CM_ SG_ 2400316999 CSC_U_No_07 "CSC号";
CM_ SG_ 2400316999 CSC_Ucell_Frame_Index_07 "当前CSC中单体电压数据帧序号";
CM_ SG_ 2400316999 CSC_Ucell_01_07 "01 电池单体电压";
CM_ SG_ 2400316999 CSC_Ucell_02_07 "02 电池单体电压";
CM_ SG_ 2400316999 CSC_Ucell_03_07 "03电池单体电压";
CM_ SG_ 2400316999 CSC_Ucell_04_07 "04  电池单体电压";
CM_ SG_ 2400316999 CSC_Ucell_05_07 "05 电池单体电压";
CM_ SG_ 2400316999 CSC_Ucell_06_07 "06 电池单体电压";
CM_ SG_ 2400316999 CSC_Ucell_07_07 "07  电池单体电压";
CM_ SG_ 2400316999 CSC_Ucell_08_07 "08 电池单体电压";
CM_ SG_ 2400316999 CSC_Ucell_09_07 "09 电池单体电压";
CM_ SG_ 2400316999 CSC_Ucell_10_07 "10 电池单体电压";
CM_ SG_ 2400316999 CSC_Ucell_11_07 "11电池单体电压";
CM_ SG_ 2400316999 CSC_Ucell_12_07 "12 电池单体电压";
CM_ SG_ 2400316999 CSC_Ucell_13_07 "13  电池单体电压";
CM_ SG_ 2400316999 CSC_Ucell_14_07 "14  电池单体电压";
CM_ SG_ 2400316999 CSC_Ucell_15_07 "15 电池单体电压";
CM_ SG_ 2400316999 CSC_Ucell_16_07 "16 电池单体电压";
CM_ SG_ 2400316999 CSC_Ucell_17_07 "17 电池单体电压";
CM_ SG_ 2400316999 CSC_Ucell_18_07 "18 电池单体电压";
CM_ SG_ 2400316999 CSC_Ucell_19_07 "19  电池单体电压";
CM_ SG_ 2400316999 CSC_Ucell_20_07 "20  电池单体电压";
CM_ SG_ 2400316999 CSC_Ucell_21_07 "21 电池单体电压";
CM_ SG_ 2400316999 CSC_Ucell_22_07 "22 电池单体电压";
CM_ SG_ 2400316999 CSC_Ucell_23_07 "23 电池单体电压";
CM_ SG_ 2400316999 CSC_Ucell_24_07 "24 电池单体电压";
CM_ SG_ 2400316999 CSC_Ucell_25_07 "25 电池单体电压";
CM_ SG_ 2400316999 CSC_Ucell_26_07 "26 电池单体电压";
CM_ SG_ 2400316999 CSC_Ucell_27_07 "27 电池单体电压";
CM_ SG_ 2400316999 CSC_Ucell_28_07 "28 电池单体电压";
CM_ SG_ 2400316999 CSC_Ucell_29_07 "29 电池单体电压";
CM_ SG_ 2400316999 CSC_Ucell_30_07 "30 电池单体电压";
CM_ SG_ 2400316999 CSC_Ucell_31_07 "31 电池单体电压";
CM_ SG_ 2400316999 CSC_Ucell_32_07 "32 电池单体电压";
CM_ SG_ 2400316999 CSC_Ucell_33_07 "33 电池单体电压";
CM_ SG_ 2400316999 CSC_Ucell_34_07 "34 电池单体电压";
CM_ SG_ 2400316999 CSC_Ucell_35_07 "35 电池单体电压";
CM_ SG_ 2400316999 CSC_Ucell_36_07 "36 电池单体电压";
CM_ SG_ 2400316999 CSC_Ucell_37_07 "37 电池单体电压";
CM_ SG_ 2400316999 CSC_Ucell_38_07 "38 电池单体电压";
CM_ SG_ 2400316999 CSC_Ucell_39_07 "39 电池单体电压";
CM_ SG_ 2400316999 CSC_Ucell_40_07 "40 电池单体电压";
CM_ SG_ 2400316999 CSC_Ucell_41_07 "41 电池单体电压";
CM_ SG_ 2400316999 CSC_Ucell_42_07 "42 电池单体电压";
CM_ SG_ 2400316999 CSC_Ucell_43_07 "43 电池单体电压";
CM_ SG_ 2400316999 CSC_Ucell_44_07 "44 电池单体电压";
CM_ SG_ 2400316999 CSC_Ucell_45_07 "45 电池单体电压";
CM_ SG_ 2400316999 CSC_Ucell_46_07 "46 电池单体电压";
CM_ SG_ 2400316999 CSC_Ucell_47_07 "47 电池单体电压";
CM_ SG_ 2400316999 CSC_Ucell_48_07 "48 电池单体电压";
CM_ SG_ 2400316999 CSC_Ucell_49_07 "49 电池单体电压";
CM_ SG_ 2400316999 CSC_Ucell_50_07 "50 电池单体电压";
CM_ SG_ 2400316999 CSC_Ucell_51_07 "51 电池单体电压";
CM_ SG_ 2400316999 CSC_Ucell_52_07 "52 电池单体电压";
CM_ SG_ 2400316999 CSC_Ucell_53_07 "53 电池单体电压";
CM_ SG_ 2400316999 CSC_Ucell_54_07 "54 电池单体电压";
CM_ SG_ 2400316999 CSC_Ucell_55_07 "55 电池单体电压";
CM_ SG_ 2400316999 CSC_Ucell_56_07 "56 电池单体电压";
CM_ SG_ 2400316999 CSC_Ucell_57_07 "57 电池单体电压";
VAL_ 2332753748 FireFault_Level1_20 0 "无故障" 1 "故障" ;
VAL_ 2332753748 FireFault_Level2_20 0 "无故障" 1 "故障" ;
VAL_ 2332753748 TempState_20 0 "无报警" 1 "温感报警" ;
VAL_ 2332753748 FogState_20 0 "无报警" 1 "烟感告警" ;
VAL_ 2332753748 AerosolState_20 0 "未触发" 1 "已触发" ;
VAL_ 2332753748 AerosolFaultState_20 0 "无故障" 1 "异常开启" 2 "异常关闭" ;
VAL_ 2332753748 DoorState_20 0 "柜门闭合" 1 "柜门开启" ;
VAL_ 2332753748 ControlBoxFanState_20 0 "未开启" 1 "已开启" ;
VAL_ 2332753748 ControlBoxTempHighWarning_20 0 "无报警" 1 "主控箱高温报警" ;
VAL_ 2332753748 PowerSWState_20 0 "未触发" 1 "已触发" ;
VAL_ 2332753748 FaultClearCommand_20 0 "不清除" 1 "清除全部极限故障" ;
VAL_ 2332753749 FireFault_Level1_21 0 "无故障" 1 "故障" ;
VAL_ 2332753749 FireFault_Level2_21 0 "无故障" 1 "故障" ;
VAL_ 2332753749 TempState_21 0 "无报警" 1 "温感报警" ;
VAL_ 2332753749 FogState_21 0 "无报警" 1 "烟感告警" ;
VAL_ 2332753749 AerosolState_21 0 "未触发" 1 "已触发" ;
VAL_ 2332753749 AerosolFaultState_21 0 "无故障" 1 "异常开启" 2 "异常关闭" ;
VAL_ 2332753749 DoorState_21 0 "柜门闭合" 1 "柜门开启" ;
VAL_ 2332753749 ControlBoxFanState_21 0 "未开启" 1 "已开启" ;
VAL_ 2332753749 ControlBoxTempHighWarning_21 0 "无报警" 1 "主控箱高温报警" ;
VAL_ 2332753749 PowerSWState_21 0 "未触发" 1 "已触发" ;
VAL_ 2332753749 FaultClearCommand_21 0 "不清除" 1 "清除全部极限故障" ;
VAL_ 2332753750 FireFault_Level1_22 0 "无故障" 1 "故障" ;
VAL_ 2332753750 FireFault_Level2_22 0 "无故障" 1 "故障" ;
VAL_ 2332753750 TempState_22 0 "无报警" 1 "温感报警" ;
VAL_ 2332753750 FogState_22 0 "无报警" 1 "烟感告警" ;
VAL_ 2332753750 AerosolState_22 0 "未触发" 1 "已触发" ;
VAL_ 2332753750 AerosolFaultState_22 0 "无故障" 1 "异常开启" 2 "异常关闭" ;
VAL_ 2332753750 DoorState_22 0 "柜门闭合" 1 "柜门开启" ;
VAL_ 2332753750 ControlBoxFanState_22 0 "未开启" 1 "已开启" ;
VAL_ 2332753750 ControlBoxTempHighWarning_22 0 "无报警" 1 "主控箱高温报警" ;
VAL_ 2332753750 PowerSWState_22 0 "未触发" 1 "已触发" ;
VAL_ 2332753750 FaultClearCommand_22 0 "不清除" 1 "清除全部极限故障" ;
VAL_ 2332753751 FireFault_Level1_23 0 "无故障" 1 "故障" ;
VAL_ 2332753751 FireFault_Level2_23 0 "无故障" 1 "故障" ;
VAL_ 2332753751 TempState_23 0 "无报警" 1 "温感报警" ;
VAL_ 2332753751 FogState_23 0 "无报警" 1 "烟感告警" ;
VAL_ 2332753751 AerosolState_23 0 "未触发" 1 "已触发" ;
VAL_ 2332753751 AerosolFaultState_23 0 "无故障" 1 "异常开启" 2 "异常关闭" ;
VAL_ 2332753751 DoorState_23 0 "柜门闭合" 1 "柜门开启" ;
VAL_ 2332753751 ControlBoxFanState_23 0 "未开启" 1 "已开启" ;
VAL_ 2332753751 ControlBoxTempHighWarning_23 0 "无报警" 1 "主控箱高温报警" ;
VAL_ 2332753751 PowerSWState_23 0 "未触发" 1 "已触发" ;
VAL_ 2332753751 FaultClearCommand_23 0 "不清除" 1 "清除全部极限故障" ;
VAL_ 2332753752 FireFault_Level1_24 0 "无故障" 1 "故障" ;
VAL_ 2332753752 FireFault_Level2_24 0 "无故障" 1 "故障" ;
VAL_ 2332753752 TempState_24 0 "无报警" 1 "温感报警" ;
VAL_ 2332753752 FogState_24 0 "无报警" 1 "烟感告警" ;
VAL_ 2332753752 AerosolState_24 0 "未触发" 1 "已触发" ;
VAL_ 2332753752 AerosolFaultState_24 0 "无故障" 1 "异常开启" 2 "异常关闭" ;
VAL_ 2332753752 DoorState_24 0 "柜门闭合" 1 "柜门开启" ;
VAL_ 2332753752 ControlBoxFanState_24 0 "未开启" 1 "已开启" ;
VAL_ 2332753752 ControlBoxTempHighWarning_24 0 "无报警" 1 "主控箱高温报警" ;
VAL_ 2332753752 PowerSWState_24 0 "未触发" 1 "已触发" ;
VAL_ 2332753752 FaultClearCommand_24 0 "不清除" 1 "清除全部极限故障" ;
VAL_ 2332753753 FireFault_Level1_25 0 "无故障" 1 "故障" ;
VAL_ 2332753753 FireFault_Level2_25 0 "无故障" 1 "故障" ;
VAL_ 2332753753 TempState_25 0 "无报警" 1 "温感报警" ;
VAL_ 2332753753 FogState_25 0 "无报警" 1 "烟感告警" ;
VAL_ 2332753753 AerosolState_25 0 "未触发" 1 "已触发" ;
VAL_ 2332753753 AerosolFaultState_25 0 "无故障" 1 "异常开启" 2 "异常关闭" ;
VAL_ 2332753753 DoorState_25 0 "柜门闭合" 1 "柜门开启" ;
VAL_ 2332753753 ControlBoxFanState_25 0 "未开启" 1 "已开启" ;
VAL_ 2332753753 ControlBoxTempHighWarning_25 0 "无报警" 1 "主控箱高温报警" ;
VAL_ 2332753753 PowerSWState_25 0 "未触发" 1 "已触发" ;
VAL_ 2332753753 FaultClearCommand_25 0 "不清除" 1 "清除全部极限故障" ;
VAL_ 2332753754 FireFault_Level1_26 0 "无故障" 1 "故障" ;
VAL_ 2332753754 FireFault_Level2_26 0 "无故障" 1 "故障" ;
VAL_ 2332753754 TempState_26 0 "无报警" 1 "温感报警" ;
VAL_ 2332753754 FogState_26 0 "无报警" 1 "烟感告警" ;
VAL_ 2332753754 AerosolState_26 0 "未触发" 1 "已触发" ;
VAL_ 2332753754 AerosolFaultState_26 0 "无故障" 1 "异常开启" 2 "异常关闭" ;
VAL_ 2332753754 DoorState_26 0 "柜门闭合" 1 "柜门开启" ;
VAL_ 2332753754 ControlBoxFanState_26 0 "未开启" 1 "已开启" ;
VAL_ 2332753754 ControlBoxTempHighWarning_26 0 "无报警" 1 "主控箱高温报警" ;
VAL_ 2332753754 PowerSWState_26 0 "未触发" 1 "已触发" ;
VAL_ 2332753754 FaultClearCommand_26 0 "不清除" 1 "清除全部极限故障" ;
VAL_ 2332753755 FireFault_Level1_27 0 "无故障" 1 "故障" ;
VAL_ 2332753755 FireFault_Level2_27 0 "无故障" 1 "故障" ;
VAL_ 2332753755 TempState_27 0 "无报警" 1 "温感报警" ;
VAL_ 2332753755 FogState_27 0 "无报警" 1 "烟感告警" ;
VAL_ 2332753755 AerosolState_27 0 "未触发" 1 "已触发" ;
VAL_ 2332753755 AerosolFaultState_27 0 "无故障" 1 "异常开启" 2 "异常关闭" ;
VAL_ 2332753755 DoorState_27 0 "柜门闭合" 1 "柜门开启" ;
VAL_ 2332753755 ControlBoxFanState_27 0 "未开启" 1 "已开启" ;
VAL_ 2332753755 ControlBoxTempHighWarning_27 0 "无报警" 1 "主控箱高温报警" ;
VAL_ 2332753755 PowerSWState_27 0 "未触发" 1 "已触发" ;
VAL_ 2332753755 FaultClearCommand_27 0 "不清除" 1 "清除全部极限故障" ;
VAL_ 2332753756 FireFault_Level1_28 0 "无故障" 1 "故障" ;
VAL_ 2332753756 FireFault_Level2_28 0 "无故障" 1 "故障" ;
VAL_ 2332753756 TempState_28 0 "无报警" 1 "温感报警" ;
VAL_ 2332753756 FogState_28 0 "无报警" 1 "烟感告警" ;
VAL_ 2332753756 AerosolState_28 0 "未触发" 1 "已触发" ;
VAL_ 2332753756 AerosolFaultState_28 0 "无故障" 1 "异常开启" 2 "异常关闭" ;
VAL_ 2332753756 DoorState_28 0 "柜门闭合" 1 "柜门开启" ;
VAL_ 2332753756 ControlBoxFanState_28 0 "未开启" 1 "已开启" ;
VAL_ 2332753756 ControlBoxTempHighWarning_28 0 "无报警" 1 "主控箱高温报警" ;
VAL_ 2332753756 PowerSWState_28 0 "未触发" 1 "已触发" ;
VAL_ 2332753756 FaultClearCommand_28 0 "不清除" 1 "清除全部极限故障" ;
VAL_ 2332753757 FireFault_Level1_29 0 "无故障" 1 "故障" ;
VAL_ 2332753757 FireFault_Level2_29 0 "无故障" 1 "故障" ;
VAL_ 2332753757 TempState_29 0 "无报警" 1 "温感报警" ;
VAL_ 2332753757 FogState_29 0 "无报警" 1 "烟感告警" ;
VAL_ 2332753757 AerosolState_29 0 "未触发" 1 "已触发" ;
VAL_ 2332753757 AerosolFaultState_29 0 "无故障" 1 "异常开启" 2 "异常关闭" ;
VAL_ 2332753757 DoorState_29 0 "柜门闭合" 1 "柜门开启" ;
VAL_ 2332753757 ControlBoxFanState_29 0 "未开启" 1 "已开启" ;
VAL_ 2332753757 ControlBoxTempHighWarning_29 0 "无报警" 1 "主控箱高温报警" ;
VAL_ 2332753757 PowerSWState_29 0 "未触发" 1 "已触发" ;
VAL_ 2332753757 FaultClearCommand_29 0 "不清除" 1 "清除全部极限故障" ;
VAL_ 2332753758 FireFault_Level1_30 0 "无故障" 1 "故障" ;
VAL_ 2332753758 FireFault_Level2_30 0 "无故障" 1 "故障" ;
VAL_ 2332753758 TempState_30 0 "无报警" 1 "温感报警" ;
VAL_ 2332753758 FogState_30 0 "无报警" 1 "烟感告警" ;
VAL_ 2332753758 AerosolState_30 0 "未触发" 1 "已触发" ;
VAL_ 2332753758 AerosolFaultState_30 0 "无故障" 1 "异常开启" 2 "异常关闭" ;
VAL_ 2332753758 DoorState_30 0 "柜门闭合" 1 "柜门开启" ;
VAL_ 2332753758 ControlBoxFanState_30 0 "未开启" 1 "已开启" ;
VAL_ 2332753758 ControlBoxTempHighWarning_30 0 "无报警" 1 "主控箱高温报警" ;
VAL_ 2332753758 PowerSWState_30 0 "未触发" 1 "已触发" ;
VAL_ 2332753758 FaultClearCommand_30 0 "不清除" 1 "清除全部极限故障" ;
VAL_ 2332753759 FireFault_Level1_31 0 "无故障" 1 "故障" ;
VAL_ 2332753759 FireFault_Level2_31 0 "无故障" 1 "故障" ;
VAL_ 2332753759 TempState_31 0 "无报警" 1 "温感报警" ;
VAL_ 2332753759 FogState_31 0 "无报警" 1 "烟感告警" ;
VAL_ 2332753759 AerosolState_31 0 "未触发" 1 "已触发" ;
VAL_ 2332753759 AerosolFaultState_31 0 "无故障" 1 "异常开启" 2 "异常关闭" ;
VAL_ 2332753759 DoorState_31 0 "柜门闭合" 1 "柜门开启" ;
VAL_ 2332753759 ControlBoxFanState_31 0 "未开启" 1 "已开启" ;
VAL_ 2332753759 ControlBoxTempHighWarning_31 0 "无报警" 1 "主控箱高温报警" ;
VAL_ 2332753759 PowerSWState_31 0 "未触发" 1 "已触发" ;
VAL_ 2332753759 FaultClearCommand_31 0 "不清除" 1 "清除全部极限故障" ;
VAL_ 2332753760 FireFault_Level1_32 0 "无故障" 1 "故障" ;
VAL_ 2332753760 FireFault_Level2_32 0 "无故障" 1 "故障" ;
VAL_ 2332753760 TempState_32 0 "无报警" 1 "温感报警" ;
VAL_ 2332753760 FogState_32 0 "无报警" 1 "烟感告警" ;
VAL_ 2332753760 AerosolState_32 0 "未触发" 1 "已触发" ;
VAL_ 2332753760 AerosolFaultState_32 0 "无故障" 1 "异常开启" 2 "异常关闭" ;
VAL_ 2332753760 DoorState_32 0 "柜门闭合" 1 "柜门开启" ;
VAL_ 2332753760 ControlBoxFanState_32 0 "未开启" 1 "已开启" ;
VAL_ 2332753760 ControlBoxTempHighWarning_32 0 "无报警" 1 "主控箱高温报警" ;
VAL_ 2332753760 PowerSWState_32 0 "未触发" 1 "已触发" ;
VAL_ 2332753760 FaultClearCommand_32 0 "不清除" 1 "清除全部极限故障" ;
VAL_ 2332753761 FireFault_Level1_33 0 "无故障" 1 "故障" ;
VAL_ 2332753761 FireFault_Level2_33 0 "无故障" 1 "故障" ;
VAL_ 2332753761 TempState_33 0 "无报警" 1 "温感报警" ;
VAL_ 2332753761 FogState_33 0 "无报警" 1 "烟感告警" ;
VAL_ 2332753761 AerosolState_33 0 "未触发" 1 "已触发" ;
VAL_ 2332753761 AerosolFaultState_33 0 "无故障" 1 "异常开启" 2 "异常关闭" ;
VAL_ 2332753761 DoorState_33 0 "柜门闭合" 1 "柜门开启" ;
VAL_ 2332753761 ControlBoxFanState_33 0 "未开启" 1 "已开启" ;
VAL_ 2332753761 ControlBoxTempHighWarning_33 0 "无报警" 1 "主控箱高温报警" ;
VAL_ 2332753761 PowerSWState_33 0 "未触发" 1 "已触发" ;
VAL_ 2332753761 FaultClearCommand_33 0 "不清除" 1 "清除全部极限故障" ;
VAL_ 2332753762 FireFault_Level1_34 0 "无故障" 1 "故障" ;
VAL_ 2332753762 FireFault_Level2_34 0 "无故障" 1 "故障" ;
VAL_ 2332753762 TempState_34 0 "无报警" 1 "温感报警" ;
VAL_ 2332753762 FogState_34 0 "无报警" 1 "烟感告警" ;
VAL_ 2332753762 AerosolState_34 0 "未触发" 1 "已触发" ;
VAL_ 2332753762 AerosolFaultState_34 0 "无故障" 1 "异常开启" 2 "异常关闭" ;
VAL_ 2332753762 DoorState_34 0 "柜门闭合" 1 "柜门开启" ;
VAL_ 2332753762 ControlBoxFanState_34 0 "未开启" 1 "已开启" ;
VAL_ 2332753762 ControlBoxTempHighWarning_34 0 "无报警" 1 "主控箱高温报警" ;
VAL_ 2332753762 PowerSWState_34 0 "未触发" 1 "已触发" ;
VAL_ 2332753762 FaultClearCommand_34 0 "不清除" 1 "清除全部极限故障" ;
VAL_ 2332753763 FireFault_Level1_35 0 "无故障" 1 "故障" ;
VAL_ 2332753763 FireFault_Level2_35 0 "无故障" 1 "故障" ;
VAL_ 2332753763 TempState_35 0 "无报警" 1 "温感报警" ;
VAL_ 2332753763 FogState_35 0 "无报警" 1 "烟感告警" ;
VAL_ 2332753763 AerosolState_35 0 "未触发" 1 "已触发" ;
VAL_ 2332753763 AerosolFaultState_35 0 "无故障" 1 "异常开启" 2 "异常关闭" ;
VAL_ 2332753763 DoorState_35 0 "柜门闭合" 1 "柜门开启" ;
VAL_ 2332753763 ControlBoxFanState_35 0 "未开启" 1 "已开启" ;
VAL_ 2332753763 ControlBoxTempHighWarning_35 0 "无报警" 1 "主控箱高温报警" ;
VAL_ 2332753763 PowerSWState_35 0 "未触发" 1 "已触发" ;
VAL_ 2332753763 FaultClearCommand_35 0 "不清除" 1 "清除全部极限故障" ;
VAL_ 2332753764 FireFault_Level1_36 0 "无故障" 1 "故障" ;
VAL_ 2332753764 FireFault_Level2_36 0 "无故障" 1 "故障" ;
VAL_ 2332753764 TempState_36 0 "无报警" 1 "温感报警" ;
VAL_ 2332753764 FogState_36 0 "无报警" 1 "烟感告警" ;
VAL_ 2332753764 AerosolState_36 0 "未触发" 1 "已触发" ;
VAL_ 2332753764 AerosolFaultState_36 0 "无故障" 1 "异常开启" 2 "异常关闭" ;
VAL_ 2332753764 DoorState_36 0 "柜门闭合" 1 "柜门开启" ;
VAL_ 2332753764 ControlBoxFanState_36 0 "未开启" 1 "已开启" ;
VAL_ 2332753764 ControlBoxTempHighWarning_36 0 "无报警" 1 "主控箱高温报警" ;
VAL_ 2332753764 PowerSWState_36 0 "未触发" 1 "已触发" ;
VAL_ 2332753764 FaultClearCommand_36 0 "不清除" 1 "清除全部极限故障" ;
VAL_ 2332753765 FireFault_Level1_37 0 "无故障" 1 "故障" ;
VAL_ 2332753765 FireFault_Level2_37 0 "无故障" 1 "故障" ;
VAL_ 2332753765 TempState_37 0 "无报警" 1 "温感报警" ;
VAL_ 2332753765 FogState_37 0 "无报警" 1 "烟感告警" ;
VAL_ 2332753765 AerosolState_37 0 "未触发" 1 "已触发" ;
VAL_ 2332753765 AerosolFaultState_37 0 "无故障" 1 "异常开启" 2 "异常关闭" ;
VAL_ 2332753765 DoorState_37 0 "柜门闭合" 1 "柜门开启" ;
VAL_ 2332753765 ControlBoxFanState_37 0 "未开启" 1 "已开启" ;
VAL_ 2332753765 ControlBoxTempHighWarning_37 0 "无报警" 1 "主控箱高温报警" ;
VAL_ 2332753765 PowerSWState_37 0 "未触发" 1 "已触发" ;
VAL_ 2332753765 FaultClearCommand_37 0 "不清除" 1 "清除全部极限故障" ;
VAL_ 2332753766 FireFault_Level1_38 0 "无故障" 1 "故障" ;
VAL_ 2332753766 FireFault_Level2_38 0 "无故障" 1 "故障" ;
VAL_ 2332753766 TempState_38 0 "无报警" 1 "温感报警" ;
VAL_ 2332753766 FogState_38 0 "无报警" 1 "烟感告警" ;
VAL_ 2332753766 AerosolState_38 0 "未触发" 1 "已触发" ;
VAL_ 2332753766 AerosolFaultState_38 0 "无故障" 1 "异常开启" 2 "异常关闭" ;
VAL_ 2332753766 DoorState_38 0 "柜门闭合" 1 "柜门开启" ;
VAL_ 2332753766 ControlBoxFanState_38 0 "未开启" 1 "已开启" ;
VAL_ 2332753766 ControlBoxTempHighWarning_38 0 "无报警" 1 "主控箱高温报警" ;
VAL_ 2332753766 PowerSWState_38 0 "未触发" 1 "已触发" ;
VAL_ 2332753766 FaultClearCommand_38 0 "不清除" 1 "清除全部极限故障" ;
VAL_ 2332753767 FireFault_Level1_39 0 "无故障" 1 "故障" ;
VAL_ 2332753767 FireFault_Level2_39 0 "无故障" 1 "故障" ;
VAL_ 2332753767 TempState_39 0 "无报警" 1 "温感报警" ;
VAL_ 2332753767 FogState_39 0 "无报警" 1 "烟感告警" ;
VAL_ 2332753767 AerosolState_39 0 "未触发" 1 "已触发" ;
VAL_ 2332753767 AerosolFaultState_39 0 "无故障" 1 "异常开启" 2 "异常关闭" ;
VAL_ 2332753767 DoorState_39 0 "柜门闭合" 1 "柜门开启" ;
VAL_ 2332753767 ControlBoxFanState_39 0 "未开启" 1 "已开启" ;
VAL_ 2332753767 ControlBoxTempHighWarning_39 0 "无报警" 1 "主控箱高温报警" ;
VAL_ 2332753767 PowerSWState_39 0 "未触发" 1 "已触发" ;
VAL_ 2332753767 FaultClearCommand_39 0 "不清除" 1 "清除全部极限故障" ;
VAL_ 2332753768 FireFault_Level1_40 0 "无故障" 1 "故障" ;
VAL_ 2332753768 FireFault_Level2_40 0 "无故障" 1 "故障" ;
VAL_ 2332753768 TempState_40 0 "无报警" 1 "温感报警" ;
VAL_ 2332753768 FogState_40 0 "无报警" 1 "烟感告警" ;
VAL_ 2332753768 AerosolState_40 0 "未触发" 1 "已触发" ;
VAL_ 2332753768 AerosolFaultState_40 0 "无故障" 1 "异常开启" 2 "异常关闭" ;
VAL_ 2332753768 DoorState_40 0 "柜门闭合" 1 "柜门开启" ;
VAL_ 2332753768 ControlBoxFanState_40 0 "未开启" 1 "已开启" ;
VAL_ 2332753768 ControlBoxTempHighWarning_40 0 "无报警" 1 "主控箱高温报警" ;
VAL_ 2332753768 PowerSWState_40 0 "未触发" 1 "已触发" ;
VAL_ 2332753768 FaultClearCommand_40 0 "不清除" 1 "清除全部极限故障" ;
VAL_ 2332753769 FireFault_Level1_41 0 "无故障" 1 "故障" ;
VAL_ 2332753769 FireFault_Level2_41 0 "无故障" 1 "故障" ;
VAL_ 2332753769 TempState_41 0 "无报警" 1 "温感报警" ;
VAL_ 2332753769 FogState_41 0 "无报警" 1 "烟感告警" ;
VAL_ 2332753769 AerosolState_41 0 "未触发" 1 "已触发" ;
VAL_ 2332753769 AerosolFaultState_41 0 "无故障" 1 "异常开启" 2 "异常关闭" ;
VAL_ 2332753769 DoorState_41 0 "柜门闭合" 1 "柜门开启" ;
VAL_ 2332753769 ControlBoxFanState_41 0 "未开启" 1 "已开启" ;
VAL_ 2332753769 ControlBoxTempHighWarning_41 0 "无报警" 1 "主控箱高温报警" ;
VAL_ 2332753769 PowerSWState_41 0 "未触发" 1 "已触发" ;
VAL_ 2332753769 FaultClearCommand_41 0 "不清除" 1 "清除全部极限故障" ;
VAL_ 2332753770 FireFault_Level1_42 0 "无故障" 1 "故障" ;
VAL_ 2332753770 FireFault_Level2_42 0 "无故障" 1 "故障" ;
VAL_ 2332753770 TempState_42 0 "无报警" 1 "温感报警" ;
VAL_ 2332753770 FogState_42 0 "无报警" 1 "烟感告警" ;
VAL_ 2332753770 AerosolState_42 0 "未触发" 1 "已触发" ;
VAL_ 2332753770 AerosolFaultState_42 0 "无故障" 1 "异常开启" 2 "异常关闭" ;
VAL_ 2332753770 DoorState_42 0 "柜门闭合" 1 "柜门开启" ;
VAL_ 2332753770 ControlBoxFanState_42 0 "未开启" 1 "已开启" ;
VAL_ 2332753770 ControlBoxTempHighWarning_42 0 "无报警" 1 "主控箱高温报警" ;
VAL_ 2332753770 PowerSWState_42 0 "未触发" 1 "已触发" ;
VAL_ 2332753770 FaultClearCommand_42 0 "不清除" 1 "清除全部极限故障" ;
VAL_ 2332753771 FireFault_Level1_43 0 "无故障" 1 "故障" ;
VAL_ 2332753771 FireFault_Level2_43 0 "无故障" 1 "故障" ;
VAL_ 2332753771 TempState_43 0 "无报警" 1 "温感报警" ;
VAL_ 2332753771 FogState_43 0 "无报警" 1 "烟感告警" ;
VAL_ 2332753771 AerosolState_43 0 "未触发" 1 "已触发" ;
VAL_ 2332753771 AerosolFaultState_43 0 "无故障" 1 "异常开启" 2 "异常关闭" ;
VAL_ 2332753771 DoorState_43 0 "柜门闭合" 1 "柜门开启" ;
VAL_ 2332753771 ControlBoxFanState_43 0 "未开启" 1 "已开启" ;
VAL_ 2332753771 ControlBoxTempHighWarning_43 0 "无报警" 1 "主控箱高温报警" ;
VAL_ 2332753771 PowerSWState_43 0 "未触发" 1 "已触发" ;
VAL_ 2332753771 FaultClearCommand_43 0 "不清除" 1 "清除全部极限故障" ;
VAL_ 2332753772 FireFault_Level1_44 0 "无故障" 1 "故障" ;
VAL_ 2332753772 FireFault_Level2_44 0 "无故障" 1 "故障" ;
VAL_ 2332753772 TempState_44 0 "无报警" 1 "温感报警" ;
VAL_ 2332753772 FogState_44 0 "无报警" 1 "烟感告警" ;
VAL_ 2332753772 AerosolState_44 0 "未触发" 1 "已触发" ;
VAL_ 2332753772 AerosolFaultState_44 0 "无故障" 1 "异常开启" 2 "异常关闭" ;
VAL_ 2332753772 DoorState_44 0 "柜门闭合" 1 "柜门开启" ;
VAL_ 2332753772 ControlBoxFanState_44 0 "未开启" 1 "已开启" ;
VAL_ 2332753772 ControlBoxTempHighWarning_44 0 "无报警" 1 "主控箱高温报警" ;
VAL_ 2332753772 PowerSWState_44 0 "未触发" 1 "已触发" ;
VAL_ 2332753772 FaultClearCommand_44 0 "不清除" 1 "清除全部极限故障" ;
VAL_ 2332753773 FireFault_Level1_45 0 "无故障" 1 "故障" ;
VAL_ 2332753773 FireFault_Level2_45 0 "无故障" 1 "故障" ;
VAL_ 2332753773 TempState_45 0 "无报警" 1 "温感报警" ;
VAL_ 2332753773 FogState_45 0 "无报警" 1 "烟感告警" ;
VAL_ 2332753773 AerosolState_45 0 "未触发" 1 "已触发" ;
VAL_ 2332753773 AerosolFaultState_45 0 "无故障" 1 "异常开启" 2 "异常关闭" ;
VAL_ 2332753773 DoorState_45 0 "柜门闭合" 1 "柜门开启" ;
VAL_ 2332753773 ControlBoxFanState_45 0 "未开启" 1 "已开启" ;
VAL_ 2332753773 ControlBoxTempHighWarning_45 0 "无报警" 1 "主控箱高温报警" ;
VAL_ 2332753773 PowerSWState_45 0 "未触发" 1 "已触发" ;
VAL_ 2332753773 FaultClearCommand_45 0 "不清除" 1 "清除全部极限故障" ;
VAL_ 2332753774 FireFault_Level1_46 0 "无故障" 1 "故障" ;
VAL_ 2332753774 FireFault_Level2_46 0 "无故障" 1 "故障" ;
VAL_ 2332753774 TempState_46 0 "无报警" 1 "温感报警" ;
VAL_ 2332753774 FogState_46 0 "无报警" 1 "烟感告警" ;
VAL_ 2332753774 AerosolState_46 0 "未触发" 1 "已触发" ;
VAL_ 2332753774 AerosolFaultState_46 0 "无故障" 1 "异常开启" 2 "异常关闭" ;
VAL_ 2332753774 DoorState_46 0 "柜门闭合" 1 "柜门开启" ;
VAL_ 2332753774 ControlBoxFanState_46 0 "未开启" 1 "已开启" ;
VAL_ 2332753774 ControlBoxTempHighWarning_46 0 "无报警" 1 "主控箱高温报警" ;
VAL_ 2332753774 PowerSWState_46 0 "未触发" 1 "已触发" ;
VAL_ 2332753774 FaultClearCommand_46 0 "不清除" 1 "清除全部极限故障" ;
VAL_ 2332753775 FireFault_Level1_47 0 "无故障" 1 "故障" ;
VAL_ 2332753775 FireFault_Level2_47 0 "无故障" 1 "故障" ;
VAL_ 2332753775 TempState_47 0 "无报警" 1 "温感报警" ;
VAL_ 2332753775 FogState_47 0 "无报警" 1 "烟感告警" ;
VAL_ 2332753775 AerosolState_47 0 "未触发" 1 "已触发" ;
VAL_ 2332753775 AerosolFaultState_47 0 "无故障" 1 "异常开启" 2 "异常关闭" ;
VAL_ 2332753775 DoorState_47 0 "柜门闭合" 1 "柜门开启" ;
VAL_ 2332753775 ControlBoxFanState_47 0 "未开启" 1 "已开启" ;
VAL_ 2332753775 ControlBoxTempHighWarning_47 0 "无报警" 1 "主控箱高温报警" ;
VAL_ 2332753775 PowerSWState_47 0 "未触发" 1 "已触发" ;
VAL_ 2332753775 FaultClearCommand_47 0 "不清除" 1 "清除全部极限故障" ;
VAL_ 2332753776 FireFault_Level1_48 0 "无故障" 1 "故障" ;
VAL_ 2332753776 FireFault_Level2_48 0 "无故障" 1 "故障" ;
VAL_ 2332753776 TempState_48 0 "无报警" 1 "温感报警" ;
VAL_ 2332753776 FogState_48 0 "无报警" 1 "烟感告警" ;
VAL_ 2332753776 AerosolState_48 0 "未触发" 1 "已触发" ;
VAL_ 2332753776 AerosolFaultState_48 0 "无故障" 1 "异常开启" 2 "异常关闭" ;
VAL_ 2332753776 DoorState_48 0 "柜门闭合" 1 "柜门开启" ;
VAL_ 2332753776 ControlBoxFanState_48 0 "未开启" 1 "已开启" ;
VAL_ 2332753776 ControlBoxTempHighWarning_48 0 "无报警" 1 "主控箱高温报警" ;
VAL_ 2332753776 PowerSWState_48 0 "未触发" 1 "已触发" ;
VAL_ 2332753776 FaultClearCommand_48 0 "不清除" 1 "清除全部极限故障" ;
VAL_ 2332753777 FireFault_Level1_49 0 "无故障" 1 "故障" ;
VAL_ 2332753777 FireFault_Level2_49 0 "无故障" 1 "故障" ;
VAL_ 2332753777 TempState_49 0 "无报警" 1 "温感报警" ;
VAL_ 2332753777 FogState_49 0 "无报警" 1 "烟感告警" ;
VAL_ 2332753777 AerosolState_49 0 "未触发" 1 "已触发" ;
VAL_ 2332753777 AerosolFaultState_49 0 "无故障" 1 "异常开启" 2 "异常关闭" ;
VAL_ 2332753777 DoorState_49 0 "柜门闭合" 1 "柜门开启" ;
VAL_ 2332753777 ControlBoxFanState_49 0 "未开启" 1 "已开启" ;
VAL_ 2332753777 ControlBoxTempHighWarning_49 0 "无报警" 1 "主控箱高温报警" ;
VAL_ 2332753777 PowerSWState_49 0 "未触发" 1 "已触发" ;
VAL_ 2332753777 FaultClearCommand_49 0 "不清除" 1 "清除全部极限故障" ;
VAL_ 2332753778 FireFault_Level1_50 0 "无故障" 1 "故障" ;
VAL_ 2332753778 FireFault_Level2_50 0 "无故障" 1 "故障" ;
VAL_ 2332753778 TempState_50 0 "无报警" 1 "温感报警" ;
VAL_ 2332753778 FogState_50 0 "无报警" 1 "烟感告警" ;
VAL_ 2332753778 AerosolState_50 0 "未触发" 1 "已触发" ;
VAL_ 2332753778 AerosolFaultState_50 0 "无故障" 1 "异常开启" 2 "异常关闭" ;
VAL_ 2332753778 DoorState_50 0 "柜门闭合" 1 "柜门开启" ;
VAL_ 2332753778 ControlBoxFanState_50 0 "未开启" 1 "已开启" ;
VAL_ 2332753778 ControlBoxTempHighWarning_50 0 "无报警" 1 "主控箱高温报警" ;
VAL_ 2332753778 PowerSWState_50 0 "未触发" 1 "已触发" ;
VAL_ 2332753778 FaultClearCommand_50 0 "不清除" 1 "清除全部极限故障" ;
VAL_ 2332753779 FireFault_Level1_51 0 "无故障" 1 "故障" ;
VAL_ 2332753779 FireFault_Level2_51 0 "无故障" 1 "故障" ;
VAL_ 2332753779 TempState_51 0 "无报警" 1 "温感报警" ;
VAL_ 2332753779 FogState_51 0 "无报警" 1 "烟感告警" ;
VAL_ 2332753779 AerosolState_51 0 "未触发" 1 "已触发" ;
VAL_ 2332753779 AerosolFaultState_51 0 "无故障" 1 "异常开启" 2 "异常关闭" ;
VAL_ 2332753779 DoorState_51 0 "柜门闭合" 1 "柜门开启" ;
VAL_ 2332753779 ControlBoxFanState_51 0 "未开启" 1 "已开启" ;
VAL_ 2332753779 ControlBoxTempHighWarning_51 0 "无报警" 1 "主控箱高温报警" ;
VAL_ 2332753779 PowerSWState_51 0 "未触发" 1 "已触发" ;
VAL_ 2332753779 FaultClearCommand_51 0 "不清除" 1 "清除全部极限故障" ;
VAL_ 2332753780 FireFault_Level1_52 0 "无故障" 1 "故障" ;
VAL_ 2332753780 FireFault_Level2_52 0 "无故障" 1 "故障" ;
VAL_ 2332753780 TempState_52 0 "无报警" 1 "温感报警" ;
VAL_ 2332753780 FogState_52 0 "无报警" 1 "烟感告警" ;
VAL_ 2332753780 AerosolState_52 0 "未触发" 1 "已触发" ;
VAL_ 2332753780 AerosolFaultState_52 0 "无故障" 1 "异常开启" 2 "异常关闭" ;
VAL_ 2332753780 DoorState_52 0 "柜门闭合" 1 "柜门开启" ;
VAL_ 2332753780 ControlBoxFanState_52 0 "未开启" 1 "已开启" ;
VAL_ 2332753780 ControlBoxTempHighWarning_52 0 "无报警" 1 "主控箱高温报警" ;
VAL_ 2332753780 PowerSWState_52 0 "未触发" 1 "已触发" ;
VAL_ 2332753780 FaultClearCommand_52 0 "不清除" 1 "清除全部极限故障" ;
VAL_ 2332753781 FireFault_Level1_53 0 "无故障" 1 "故障" ;
VAL_ 2332753781 FireFault_Level2_53 0 "无故障" 1 "故障" ;
VAL_ 2332753781 TempState_53 0 "无报警" 1 "温感报警" ;
VAL_ 2332753781 FogState_53 0 "无报警" 1 "烟感告警" ;
VAL_ 2332753781 AerosolState_53 0 "未触发" 1 "已触发" ;
VAL_ 2332753781 AerosolFaultState_53 0 "无故障" 1 "异常开启" 2 "异常关闭" ;
VAL_ 2332753781 DoorState_53 0 "柜门闭合" 1 "柜门开启" ;
VAL_ 2332753781 ControlBoxFanState_53 0 "未开启" 1 "已开启" ;
VAL_ 2332753781 ControlBoxTempHighWarning_53 0 "无报警" 1 "主控箱高温报警" ;
VAL_ 2332753781 PowerSWState_53 0 "未触发" 1 "已触发" ;
VAL_ 2332753781 FaultClearCommand_53 0 "不清除" 1 "清除全部极限故障" ;
VAL_ 2332753782 FireFault_Level1_54 0 "无故障" 1 "故障" ;
VAL_ 2332753782 FireFault_Level2_54 0 "无故障" 1 "故障" ;
VAL_ 2332753782 TempState_54 0 "无报警" 1 "温感报警" ;
VAL_ 2332753782 FogState_54 0 "无报警" 1 "烟感告警" ;
VAL_ 2332753782 AerosolState_54 0 "未触发" 1 "已触发" ;
VAL_ 2332753782 AerosolFaultState_54 0 "无故障" 1 "异常开启" 2 "异常关闭" ;
VAL_ 2332753782 DoorState_54 0 "柜门闭合" 1 "柜门开启" ;
VAL_ 2332753782 ControlBoxFanState_54 0 "未开启" 1 "已开启" ;
VAL_ 2332753782 ControlBoxTempHighWarning_54 0 "无报警" 1 "主控箱高温报警" ;
VAL_ 2332753782 PowerSWState_54 0 "未触发" 1 "已触发" ;
VAL_ 2332753782 FaultClearCommand_54 0 "不清除" 1 "清除全部极限故障" ;
VAL_ 2332753783 FireFault_Level1_55 0 "无故障" 1 "故障" ;
VAL_ 2332753783 FireFault_Level2_55 0 "无故障" 1 "故障" ;
VAL_ 2332753783 TempState_55 0 "无报警" 1 "温感报警" ;
VAL_ 2332753783 FogState_55 0 "无报警" 1 "烟感告警" ;
VAL_ 2332753783 AerosolState_55 0 "未触发" 1 "已触发" ;
VAL_ 2332753783 AerosolFaultState_55 0 "无故障" 1 "异常开启" 2 "异常关闭" ;
VAL_ 2332753783 DoorState_55 0 "柜门闭合" 1 "柜门开启" ;
VAL_ 2332753783 ControlBoxFanState_55 0 "未开启" 1 "已开启" ;
VAL_ 2332753783 ControlBoxTempHighWarning_55 0 "无报警" 1 "主控箱高温报警" ;
VAL_ 2332753783 PowerSWState_55 0 "未触发" 1 "已触发" ;
VAL_ 2332753783 FaultClearCommand_55 0 "不清除" 1 "清除全部极限故障" ;
VAL_ 2332753784 FireFault_Level1_56 0 "无故障" 1 "故障" ;
VAL_ 2332753784 FireFault_Level2_56 0 "无故障" 1 "故障" ;
VAL_ 2332753784 TempState_56 0 "无报警" 1 "温感报警" ;
VAL_ 2332753784 FogState_56 0 "无报警" 1 "烟感告警" ;
VAL_ 2332753784 AerosolState_56 0 "未触发" 1 "已触发" ;
VAL_ 2332753784 AerosolFaultState_56 0 "无故障" 1 "异常开启" 2 "异常关闭" ;
VAL_ 2332753784 DoorState_56 0 "柜门闭合" 1 "柜门开启" ;
VAL_ 2332753784 ControlBoxFanState_56 0 "未开启" 1 "已开启" ;
VAL_ 2332753784 ControlBoxTempHighWarning_56 0 "无报警" 1 "主控箱高温报警" ;
VAL_ 2332753784 PowerSWState_56 0 "未触发" 1 "已触发" ;
VAL_ 2332753784 FaultClearCommand_56 0 "不清除" 1 "清除全部极限故障" ;
VAL_ 2332753785 FireFault_Level1_57 0 "无故障" 1 "故障" ;
VAL_ 2332753785 FireFault_Level2_57 0 "无故障" 1 "故障" ;
VAL_ 2332753785 TempState_57 0 "无报警" 1 "温感报警" ;
VAL_ 2332753785 FogState_57 0 "无报警" 1 "烟感告警" ;
VAL_ 2332753785 AerosolState_57 0 "未触发" 1 "已触发" ;
VAL_ 2332753785 AerosolFaultState_57 0 "无故障" 1 "异常开启" 2 "异常关闭" ;
VAL_ 2332753785 DoorState_57 0 "柜门闭合" 1 "柜门开启" ;
VAL_ 2332753785 ControlBoxFanState_57 0 "未开启" 1 "已开启" ;
VAL_ 2332753785 ControlBoxTempHighWarning_57 0 "无报警" 1 "主控箱高温报警" ;
VAL_ 2332753785 PowerSWState_57 0 "未触发" 1 "已触发" ;
VAL_ 2332753785 FaultClearCommand_57 0 "不清除" 1 "清除全部极限故障" ;
VAL_ 2332753786 FireFault_Level1_58 0 "无故障" 1 "故障" ;
VAL_ 2332753786 FireFault_Level2_58 0 "无故障" 1 "故障" ;
VAL_ 2332753786 TempState_58 0 "无报警" 1 "温感报警" ;
VAL_ 2332753786 FogState_58 0 "无报警" 1 "烟感告警" ;
VAL_ 2332753786 AerosolState_58 0 "未触发" 1 "已触发" ;
VAL_ 2332753786 AerosolFaultState_58 0 "无故障" 1 "异常开启" 2 "异常关闭" ;
VAL_ 2332753786 DoorState_58 0 "柜门闭合" 1 "柜门开启" ;
VAL_ 2332753786 ControlBoxFanState_58 0 "未开启" 1 "已开启" ;
VAL_ 2332753786 ControlBoxTempHighWarning_58 0 "无报警" 1 "主控箱高温报警" ;
VAL_ 2332753786 PowerSWState_58 0 "未触发" 1 "已触发" ;
VAL_ 2332753786 FaultClearCommand_58 0 "不清除" 1 "清除全部极限故障" ;
VAL_ 2332753787 FireFault_Level1_59 0 "无故障" 1 "故障" ;
VAL_ 2332753787 FireFault_Level2_59 0 "无故障" 1 "故障" ;
VAL_ 2332753787 TempState_59 0 "无报警" 1 "温感报警" ;
VAL_ 2332753787 FogState_59 0 "无报警" 1 "烟感告警" ;
VAL_ 2332753787 AerosolState_59 0 "未触发" 1 "已触发" ;
VAL_ 2332753787 AerosolFaultState_59 0 "无故障" 1 "异常开启" 2 "异常关闭" ;
VAL_ 2332753787 DoorState_59 0 "柜门闭合" 1 "柜门开启" ;
VAL_ 2332753787 ControlBoxFanState_59 0 "未开启" 1 "已开启" ;
VAL_ 2332753787 ControlBoxTempHighWarning_59 0 "无报警" 1 "主控箱高温报警" ;
VAL_ 2332753787 PowerSWState_59 0 "未触发" 1 "已触发" ;
VAL_ 2332753787 FaultClearCommand_59 0 "不清除" 1 "清除全部极限故障" ;
VAL_ 2332753788 FireFault_Level1_60 0 "无故障" 1 "故障" ;
VAL_ 2332753788 FireFault_Level2_60 0 "无故障" 1 "故障" ;
VAL_ 2332753788 TempState_60 0 "无报警" 1 "温感报警" ;
VAL_ 2332753788 FogState_60 0 "无报警" 1 "烟感告警" ;
VAL_ 2332753788 AerosolState_60 0 "未触发" 1 "已触发" ;
VAL_ 2332753788 AerosolFaultState_60 0 "无故障" 1 "异常开启" 2 "异常关闭" ;
VAL_ 2332753788 DoorState_60 0 "柜门闭合" 1 "柜门开启" ;
VAL_ 2332753788 ControlBoxFanState_60 0 "未开启" 1 "已开启" ;
VAL_ 2332753788 ControlBoxTempHighWarning_60 0 "无报警" 1 "主控箱高温报警" ;
VAL_ 2332753788 PowerSWState_60 0 "未触发" 1 "已触发" ;
VAL_ 2332753788 FaultClearCommand_60 0 "不清除" 1 "清除全部极限故障" ;
VAL_ 2332753789 FireFault_Level1_61 0 "无故障" 1 "故障" ;
VAL_ 2332753789 FireFault_Level2_61 0 "无故障" 1 "故障" ;
VAL_ 2332753789 TempState_61 0 "无报警" 1 "温感报警" ;
VAL_ 2332753789 FogState_61 0 "无报警" 1 "烟感告警" ;
VAL_ 2332753789 AerosolState_61 0 "未触发" 1 "已触发" ;
VAL_ 2332753789 AerosolFaultState_61 0 "无故障" 1 "异常开启" 2 "异常关闭" ;
VAL_ 2332753789 DoorState_61 0 "柜门闭合" 1 "柜门开启" ;
VAL_ 2332753789 ControlBoxFanState_61 0 "未开启" 1 "已开启" ;
VAL_ 2332753789 ControlBoxTempHighWarning_61 0 "无报警" 1 "主控箱高温报警" ;
VAL_ 2332753789 PowerSWState_61 0 "未触发" 1 "已触发" ;
VAL_ 2332753789 FaultClearCommand_61 0 "不清除" 1 "清除全部极限故障" ;
VAL_ 2332753790 FireFault_Level1_62 0 "无故障" 1 "故障" ;
VAL_ 2332753790 FireFault_Level2_62 0 "无故障" 1 "故障" ;
VAL_ 2332753790 TempState_62 0 "无报警" 1 "温感报警" ;
VAL_ 2332753790 FogState_62 0 "无报警" 1 "烟感告警" ;
VAL_ 2332753790 AerosolState_62 0 "未触发" 1 "已触发" ;
VAL_ 2332753790 AerosolFaultState_62 0 "无故障" 1 "异常开启" 2 "异常关闭" ;
VAL_ 2332753790 DoorState_62 0 "柜门闭合" 1 "柜门开启" ;
VAL_ 2332753790 ControlBoxFanState_62 0 "未开启" 1 "已开启" ;
VAL_ 2332753790 ControlBoxTempHighWarning_62 0 "无报警" 1 "主控箱高温报警" ;
VAL_ 2332753790 PowerSWState_62 0 "未触发" 1 "已触发" ;
VAL_ 2332753790 FaultClearCommand_62 0 "不清除" 1 "清除全部极限故障" ;
VAL_ 2332753791 FireFault_Level1_63 0 "无故障" 1 "故障" ;
VAL_ 2332753791 FireFault_Level2_63 0 "无故障" 1 "故障" ;
VAL_ 2332753791 TempState_63 0 "无报警" 1 "温感报警" ;
VAL_ 2332753791 FogState_63 0 "无报警" 1 "烟感告警" ;
VAL_ 2332753791 AerosolState_63 0 "未触发" 1 "已触发" ;
VAL_ 2332753791 AerosolFaultState_63 0 "无故障" 1 "异常开启" 2 "异常关闭" ;
VAL_ 2332753791 DoorState_63 0 "柜门闭合" 1 "柜门开启" ;
VAL_ 2332753791 ControlBoxFanState_63 0 "未开启" 1 "已开启" ;
VAL_ 2332753791 ControlBoxTempHighWarning_63 0 "无报警" 1 "主控箱高温报警" ;
VAL_ 2332753791 PowerSWState_63 0 "未触发" 1 "已触发" ;
VAL_ 2332753791 FaultClearCommand_63 0 "不清除" 1 "清除全部极限故障" ;
VAL_ 2467491393 S2P_Index_ST_01 0 "Normal" 1 "CSCNoSilent" 2 "CSCNoAnswer" 3 "NoLastCodeLine" 4 "CSCNumWrong" 5 "RelayClosedOrISysIsnotZero" 6 "MatchCodeWrong" 7 "CSCSAnswerIsNoChange" ;
VAL_ 2467491393 S2P_Index_Err_01 0 "Normal " 1 "No.1CSC " 2 "No.2 CSC" ;
VAL_ 2467491394 S2P_Index_ST_02 0 "Normal" 1 "CSCNoSilent" 2 "CSCNoAnswer" 3 "NoLastCodeLine" 4 "CSCNumWrong" 5 "RelayClosedOrISysIsnotZero" 6 "MatchCodeWrong" 7 "CSCSAnswerIsNoChange" ;
VAL_ 2467491394 S2P_Index_Err_02 0 "Normal " 1 "No.1CSC " 2 "No.2 CSC" ;
VAL_ 2467491395 S2P_Index_ST_03 0 "Normal" 1 "CSCNoSilent" 2 "CSCNoAnswer" 3 "NoLastCodeLine" 4 "CSCNumWrong" 5 "RelayClosedOrISysIsnotZero" 6 "MatchCodeWrong" 7 "CSCSAnswerIsNoChange" ;
VAL_ 2467491395 S2P_Index_Err_03 0 "Normal " 1 "No.1CSC " 2 "No.2 CSC" ;
VAL_ 2467491396 S2P_Index_ST_04 0 "Normal" 1 "CSCNoSilent" 2 "CSCNoAnswer" 3 "NoLastCodeLine" 4 "CSCNumWrong" 5 "RelayClosedOrISysIsnotZero" 6 "MatchCodeWrong" 7 "CSCSAnswerIsNoChange" ;
VAL_ 2467491396 S2P_Index_Err_04 0 "Normal " 1 "No.1CSC " 2 "No.2 CSC" ;
VAL_ 2467491397 S2P_Index_ST_05 0 "Normal" 1 "CSCNoSilent" 2 "CSCNoAnswer" 3 "NoLastCodeLine" 4 "CSCNumWrong" 5 "RelayClosedOrISysIsnotZero" 6 "MatchCodeWrong" 7 "CSCSAnswerIsNoChange" ;
VAL_ 2467491397 S2P_Index_Err_05 0 "Normal " 1 "No.1CSC " 2 "No.2 CSC" ;
VAL_ 2467491398 S2P_Index_ST_06 0 "Normal" 1 "CSCNoSilent" 2 "CSCNoAnswer" 3 "NoLastCodeLine" 4 "CSCNumWrong" 5 "RelayClosedOrISysIsnotZero" 6 "MatchCodeWrong" 7 "CSCSAnswerIsNoChange" ;
VAL_ 2467491398 S2P_Index_Err_06 0 "Normal " 1 "No.1CSC " 2 "No.2 CSC" ;
VAL_ 2467491399 S2P_Index_ST_07 0 "Normal" 1 "CSCNoSilent" 2 "CSCNoAnswer" 3 "NoLastCodeLine" 4 "CSCNumWrong" 5 "RelayClosedOrISysIsnotZero" 6 "MatchCodeWrong" 7 "CSCSAnswerIsNoChange" ;
VAL_ 2467491399 S2P_Index_Err_07 0 "Normal " 1 "No.1CSC " 2 "No.2 CSC" ;
VAL_ 2467491400 S2P_Index_ST_08 0 "Normal" 1 "CSCNoSilent" 2 "CSCNoAnswer" 3 "NoLastCodeLine" 4 "CSCNumWrong" 5 "RelayClosedOrISysIsnotZero" 6 "MatchCodeWrong" 7 "CSCSAnswerIsNoChange" ;
VAL_ 2467491400 S2P_Index_Err_08 0 "Normal " 1 "No.1CSC " 2 "No.2 CSC" ;
VAL_ 2467491401 S2P_Index_ST_09 0 "Normal" 1 "CSCNoSilent" 2 "CSCNoAnswer" 3 "NoLastCodeLine" 4 "CSCNumWrong" 5 "RelayClosedOrISysIsnotZero" 6 "MatchCodeWrong" 7 "CSCSAnswerIsNoChange" ;
VAL_ 2467491401 S2P_Index_Err_09 0 "Normal " 1 "No.1CSC " 2 "No.2 CSC" ;
VAL_ 2467491402 S2P_Index_ST_10 0 "Normal" 1 "CSCNoSilent" 2 "CSCNoAnswer" 3 "NoLastCodeLine" 4 "CSCNumWrong" 5 "RelayClosedOrISysIsnotZero" 6 "MatchCodeWrong" 7 "CSCSAnswerIsNoChange" ;
VAL_ 2467491402 S2P_Index_Err_10 0 "Normal " 1 "No.1CSC " 2 "No.2 CSC" ;
VAL_ 2467491403 S2P_Index_ST_11 0 "Normal" 1 "CSCNoSilent" 2 "CSCNoAnswer" 3 "NoLastCodeLine" 4 "CSCNumWrong" 5 "RelayClosedOrISysIsnotZero" 6 "MatchCodeWrong" 7 "CSCSAnswerIsNoChange" ;
VAL_ 2467491403 S2P_Index_Err_11 0 "Normal " 1 "No.1CSC " 2 "No.2 CSC" ;
VAL_ 2467491404 S2P_Index_ST_12 0 "Normal" 1 "CSCNoSilent" 2 "CSCNoAnswer" 3 "NoLastCodeLine" 4 "CSCNumWrong" 5 "RelayClosedOrISysIsnotZero" 6 "MatchCodeWrong" 7 "CSCSAnswerIsNoChange" ;
VAL_ 2467491404 S2P_Index_Err_12 0 "Normal " 1 "No.1CSC " 2 "No.2 CSC" ;
VAL_ 2467491405 S2P_Index_ST_13 0 "Normal" 1 "CSCNoSilent" 2 "CSCNoAnswer" 3 "NoLastCodeLine" 4 "CSCNumWrong" 5 "RelayClosedOrISysIsnotZero" 6 "MatchCodeWrong" 7 "CSCSAnswerIsNoChange" ;
VAL_ 2467491405 S2P_Index_Err_13 0 "Normal " 1 "No.1CSC " 2 "No.2 CSC" ;
VAL_ 2467491406 S2P_Index_ST_14 0 "Normal" 1 "CSCNoSilent" 2 "CSCNoAnswer" 3 "NoLastCodeLine" 4 "CSCNumWrong" 5 "RelayClosedOrISysIsnotZero" 6 "MatchCodeWrong" 7 "CSCSAnswerIsNoChange" ;
VAL_ 2467491406 S2P_Index_Err_14 0 "Normal " 1 "No.1CSC " 2 "No.2 CSC" ;
VAL_ 2467491407 S2P_Index_ST_15 0 "Normal" 1 "CSCNoSilent" 2 "CSCNoAnswer" 3 "NoLastCodeLine" 4 "CSCNumWrong" 5 "RelayClosedOrISysIsnotZero" 6 "MatchCodeWrong" 7 "CSCSAnswerIsNoChange" ;
VAL_ 2467491407 S2P_Index_Err_15 0 "Normal " 1 "No.1CSC " 2 "No.2 CSC" ;
VAL_ 2467491408 S2P_Index_ST_16 0 "Normal" 1 "CSCNoSilent" 2 "CSCNoAnswer" 3 "NoLastCodeLine" 4 "CSCNumWrong" 5 "RelayClosedOrISysIsnotZero" 6 "MatchCodeWrong" 7 "CSCSAnswerIsNoChange" ;
VAL_ 2467491408 S2P_Index_Err_16 0 "Normal " 1 "No.1CSC " 2 "No.2 CSC" ;
VAL_ 2467491409 S2P_Index_ST_17 0 "Normal" 1 "CSCNoSilent" 2 "CSCNoAnswer" 3 "NoLastCodeLine" 4 "CSCNumWrong" 5 "RelayClosedOrISysIsnotZero" 6 "MatchCodeWrong" 7 "CSCSAnswerIsNoChange" ;
VAL_ 2467491409 S2P_Index_Err_17 0 "Normal " 1 "No.1CSC " 2 "No.2 CSC" ;
VAL_ 2467491410 S2P_Index_ST_18 0 "Normal" 1 "CSCNoSilent" 2 "CSCNoAnswer" 3 "NoLastCodeLine" 4 "CSCNumWrong" 5 "RelayClosedOrISysIsnotZero" 6 "MatchCodeWrong" 7 "CSCSAnswerIsNoChange" ;
VAL_ 2467491410 S2P_Index_Err_18 0 "Normal " 1 "No.1CSC " 2 "No.2 CSC" ;
VAL_ 2467491411 S2P_Index_ST_19 0 "Normal" 1 "CSCNoSilent" 2 "CSCNoAnswer" 3 "NoLastCodeLine" 4 "CSCNumWrong" 5 "RelayClosedOrISysIsnotZero" 6 "MatchCodeWrong" 7 "CSCSAnswerIsNoChange" ;
VAL_ 2467491411 S2P_Index_Err_19 0 "Normal " 1 "No.1CSC " 2 "No.2 CSC" ;
VAL_ 2467491412 S2P_Index_ST_20 0 "Normal" 1 "CSCNoSilent" 2 "CSCNoAnswer" 3 "NoLastCodeLine" 4 "CSCNumWrong" 5 "RelayClosedOrISysIsnotZero" 6 "MatchCodeWrong" 7 "CSCSAnswerIsNoChange" ;
VAL_ 2467491412 S2P_Index_Err_20 0 "Normal " 1 "No.1CSC " 2 "No.2 CSC" ;
VAL_ 2467491413 S2P_Index_ST_21 0 "Normal" 1 "CSCNoSilent" 2 "CSCNoAnswer" 3 "NoLastCodeLine" 4 "CSCNumWrong" 5 "RelayClosedOrISysIsnotZero" 6 "MatchCodeWrong" 7 "CSCSAnswerIsNoChange" ;
VAL_ 2467491413 S2P_Index_Err_21 0 "Normal " 1 "No.1CSC " 2 "No.2 CSC" ;
VAL_ 2467491414 S2P_Index_ST_22 0 "Normal" 1 "CSCNoSilent" 2 "CSCNoAnswer" 3 "NoLastCodeLine" 4 "CSCNumWrong" 5 "RelayClosedOrISysIsnotZero" 6 "MatchCodeWrong" 7 "CSCSAnswerIsNoChange" ;
VAL_ 2467491414 S2P_Index_Err_22 0 "Normal " 1 "No.1CSC " 2 "No.2 CSC" ;
VAL_ 2467491415 S2P_Index_ST_23 0 "Normal" 1 "CSCNoSilent" 2 "CSCNoAnswer" 3 "NoLastCodeLine" 4 "CSCNumWrong" 5 "RelayClosedOrISysIsnotZero" 6 "MatchCodeWrong" 7 "CSCSAnswerIsNoChange" ;
VAL_ 2467491415 S2P_Index_Err_23 0 "Normal " 1 "No.1CSC " 2 "No.2 CSC" ;
VAL_ 2467491416 S2P_Index_ST_24 0 "Normal" 1 "CSCNoSilent" 2 "CSCNoAnswer" 3 "NoLastCodeLine" 4 "CSCNumWrong" 5 "RelayClosedOrISysIsnotZero" 6 "MatchCodeWrong" 7 "CSCSAnswerIsNoChange" ;
VAL_ 2467491416 S2P_Index_Err_24 0 "Normal " 1 "No.1CSC " 2 "No.2 CSC" ;
VAL_ 2467491417 S2P_Index_ST_25 0 "Normal" 1 "CSCNoSilent" 2 "CSCNoAnswer" 3 "NoLastCodeLine" 4 "CSCNumWrong" 5 "RelayClosedOrISysIsnotZero" 6 "MatchCodeWrong" 7 "CSCSAnswerIsNoChange" ;
VAL_ 2467491417 S2P_Index_Err_25 0 "Normal " 1 "No.1CSC " 2 "No.2 CSC" ;
VAL_ 2467491418 S2P_Index_ST_26 0 "Normal" 1 "CSCNoSilent" 2 "CSCNoAnswer" 3 "NoLastCodeLine" 4 "CSCNumWrong" 5 "RelayClosedOrISysIsnotZero" 6 "MatchCodeWrong" 7 "CSCSAnswerIsNoChange" ;
VAL_ 2467491418 S2P_Index_Err_26 0 "Normal " 1 "No.1CSC " 2 "No.2 CSC" ;
VAL_ 2467491419 S2P_Index_ST_27 0 "Normal" 1 "CSCNoSilent" 2 "CSCNoAnswer" 3 "NoLastCodeLine" 4 "CSCNumWrong" 5 "RelayClosedOrISysIsnotZero" 6 "MatchCodeWrong" 7 "CSCSAnswerIsNoChange" ;
VAL_ 2467491419 S2P_Index_Err_27 0 "Normal " 1 "No.1CSC " 2 "No.2 CSC" ;
VAL_ 2467491420 S2P_Index_ST_28 0 "Normal" 1 "CSCNoSilent" 2 "CSCNoAnswer" 3 "NoLastCodeLine" 4 "CSCNumWrong" 5 "RelayClosedOrISysIsnotZero" 6 "MatchCodeWrong" 7 "CSCSAnswerIsNoChange" ;
VAL_ 2467491420 S2P_Index_Err_28 0 "Normal " 1 "No.1CSC " 2 "No.2 CSC" ;
VAL_ 2467491421 S2P_Index_ST_29 0 "Normal" 1 "CSCNoSilent" 2 "CSCNoAnswer" 3 "NoLastCodeLine" 4 "CSCNumWrong" 5 "RelayClosedOrISysIsnotZero" 6 "MatchCodeWrong" 7 "CSCSAnswerIsNoChange" ;
VAL_ 2467491421 S2P_Index_Err_29 0 "Normal " 1 "No.1CSC " 2 "No.2 CSC" ;
VAL_ 2467491422 S2P_Index_ST_30 0 "Normal" 1 "CSCNoSilent" 2 "CSCNoAnswer" 3 "NoLastCodeLine" 4 "CSCNumWrong" 5 "RelayClosedOrISysIsnotZero" 6 "MatchCodeWrong" 7 "CSCSAnswerIsNoChange" ;
VAL_ 2467491422 S2P_Index_Err_30 0 "Normal " 1 "No.1CSC " 2 "No.2 CSC" ;
VAL_ 2467491423 S2P_Index_ST_31 0 "Normal" 1 "CSCNoSilent" 2 "CSCNoAnswer" 3 "NoLastCodeLine" 4 "CSCNumWrong" 5 "RelayClosedOrISysIsnotZero" 6 "MatchCodeWrong" 7 "CSCSAnswerIsNoChange" ;
VAL_ 2467491423 S2P_Index_Err_31 0 "Normal " 1 "No.1CSC " 2 "No.2 CSC" ;
VAL_ 2467491424 S2P_Index_ST_32 0 "Normal" 1 "CSCNoSilent" 2 "CSCNoAnswer" 3 "NoLastCodeLine" 4 "CSCNumWrong" 5 "RelayClosedOrISysIsnotZero" 6 "MatchCodeWrong" 7 "CSCSAnswerIsNoChange" ;
VAL_ 2467491424 S2P_Index_Err_32 0 "Normal " 1 "No.1CSC " 2 "No.2 CSC" ;
VAL_ 2467491425 S2P_Index_ST_33 0 "Normal" 1 "CSCNoSilent" 2 "CSCNoAnswer" 3 "NoLastCodeLine" 4 "CSCNumWrong" 5 "RelayClosedOrISysIsnotZero" 6 "MatchCodeWrong" 7 "CSCSAnswerIsNoChange" ;
VAL_ 2467491425 S2P_Index_Err_33 0 "Normal " 1 "No.1CSC " 2 "No.2 CSC" ;
VAL_ 2467491426 S2P_Index_ST_34 0 "Normal" 1 "CSCNoSilent" 2 "CSCNoAnswer" 3 "NoLastCodeLine" 4 "CSCNumWrong" 5 "RelayClosedOrISysIsnotZero" 6 "MatchCodeWrong" 7 "CSCSAnswerIsNoChange" ;
VAL_ 2467491426 S2P_Index_Err_34 0 "Normal " 1 "No.1CSC " 2 "No.2 CSC" ;
VAL_ 2467491427 S2P_Index_ST_35 0 "Normal" 1 "CSCNoSilent" 2 "CSCNoAnswer" 3 "NoLastCodeLine" 4 "CSCNumWrong" 5 "RelayClosedOrISysIsnotZero" 6 "MatchCodeWrong" 7 "CSCSAnswerIsNoChange" ;
VAL_ 2467491427 S2P_Index_Err_35 0 "Normal " 1 "No.1CSC " 2 "No.2 CSC" ;
VAL_ 2467491428 S2P_Index_ST_36 0 "Normal" 1 "CSCNoSilent" 2 "CSCNoAnswer" 3 "NoLastCodeLine" 4 "CSCNumWrong" 5 "RelayClosedOrISysIsnotZero" 6 "MatchCodeWrong" 7 "CSCSAnswerIsNoChange" ;
VAL_ 2467491428 S2P_Index_Err_36 0 "Normal " 1 "No.1CSC " 2 "No.2 CSC" ;
VAL_ 2467491429 S2P_Index_ST_37 0 "Normal" 1 "CSCNoSilent" 2 "CSCNoAnswer" 3 "NoLastCodeLine" 4 "CSCNumWrong" 5 "RelayClosedOrISysIsnotZero" 6 "MatchCodeWrong" 7 "CSCSAnswerIsNoChange" ;
VAL_ 2467491429 S2P_Index_Err_37 0 "Normal " 1 "No.1CSC " 2 "No.2 CSC" ;
VAL_ 2467491430 S2P_Index_ST_38 0 "Normal" 1 "CSCNoSilent" 2 "CSCNoAnswer" 3 "NoLastCodeLine" 4 "CSCNumWrong" 5 "RelayClosedOrISysIsnotZero" 6 "MatchCodeWrong" 7 "CSCSAnswerIsNoChange" ;
VAL_ 2467491430 S2P_Index_Err_38 0 "Normal " 1 "No.1CSC " 2 "No.2 CSC" ;
VAL_ 2467491431 S2P_Index_ST_39 0 "Normal" 1 "CSCNoSilent" 2 "CSCNoAnswer" 3 "NoLastCodeLine" 4 "CSCNumWrong" 5 "RelayClosedOrISysIsnotZero" 6 "MatchCodeWrong" 7 "CSCSAnswerIsNoChange" ;
VAL_ 2467491431 S2P_Index_Err_39 0 "Normal " 1 "No.1CSC " 2 "No.2 CSC" ;
VAL_ 2467491432 S2P_Index_ST_40 0 "Normal" 1 "CSCNoSilent" 2 "CSCNoAnswer" 3 "NoLastCodeLine" 4 "CSCNumWrong" 5 "RelayClosedOrISysIsnotZero" 6 "MatchCodeWrong" 7 "CSCSAnswerIsNoChange" ;
VAL_ 2467491432 S2P_Index_Err_40 0 "Normal " 1 "No.1CSC " 2 "No.2 CSC" ;
VAL_ 2467491433 S2P_Index_ST_41 0 "Normal" 1 "CSCNoSilent" 2 "CSCNoAnswer" 3 "NoLastCodeLine" 4 "CSCNumWrong" 5 "RelayClosedOrISysIsnotZero" 6 "MatchCodeWrong" 7 "CSCSAnswerIsNoChange" ;
VAL_ 2467491433 S2P_Index_Err_41 0 "Normal " 1 "No.1CSC " 2 "No.2 CSC" ;
VAL_ 2467491434 S2P_Index_ST_42 0 "Normal" 1 "CSCNoSilent" 2 "CSCNoAnswer" 3 "NoLastCodeLine" 4 "CSCNumWrong" 5 "RelayClosedOrISysIsnotZero" 6 "MatchCodeWrong" 7 "CSCSAnswerIsNoChange" ;
VAL_ 2467491434 S2P_Index_Err_42 0 "Normal " 1 "No.1CSC " 2 "No.2 CSC" ;
VAL_ 2467491435 S2P_Index_ST_43 0 "Normal" 1 "CSCNoSilent" 2 "CSCNoAnswer" 3 "NoLastCodeLine" 4 "CSCNumWrong" 5 "RelayClosedOrISysIsnotZero" 6 "MatchCodeWrong" 7 "CSCSAnswerIsNoChange" ;
VAL_ 2467491435 S2P_Index_Err_43 0 "Normal " 1 "No.1CSC " 2 "No.2 CSC" ;
VAL_ 2467491436 S2P_Index_ST_44 0 "Normal" 1 "CSCNoSilent" 2 "CSCNoAnswer" 3 "NoLastCodeLine" 4 "CSCNumWrong" 5 "RelayClosedOrISysIsnotZero" 6 "MatchCodeWrong" 7 "CSCSAnswerIsNoChange" ;
VAL_ 2467491436 S2P_Index_Err_44 0 "Normal " 1 "No.1CSC " 2 "No.2 CSC" ;
VAL_ 2467491437 S2P_Index_ST_45 0 "Normal" 1 "CSCNoSilent" 2 "CSCNoAnswer" 3 "NoLastCodeLine" 4 "CSCNumWrong" 5 "RelayClosedOrISysIsnotZero" 6 "MatchCodeWrong" 7 "CSCSAnswerIsNoChange" ;
VAL_ 2467491437 S2P_Index_Err_45 0 "Normal " 1 "No.1CSC " 2 "No.2 CSC" ;
VAL_ 2467491438 S2P_Index_ST_46 0 "Normal" 1 "CSCNoSilent" 2 "CSCNoAnswer" 3 "NoLastCodeLine" 4 "CSCNumWrong" 5 "RelayClosedOrISysIsnotZero" 6 "MatchCodeWrong" 7 "CSCSAnswerIsNoChange" ;
VAL_ 2467491438 S2P_Index_Err_46 0 "Normal " 1 "No.1CSC " 2 "No.2 CSC" ;
VAL_ 2467491439 S2P_Index_ST_47 0 "Normal" 1 "CSCNoSilent" 2 "CSCNoAnswer" 3 "NoLastCodeLine" 4 "CSCNumWrong" 5 "RelayClosedOrISysIsnotZero" 6 "MatchCodeWrong" 7 "CSCSAnswerIsNoChange" ;
VAL_ 2467491439 S2P_Index_Err_47 0 "Normal " 1 "No.1CSC " 2 "No.2 CSC" ;
VAL_ 2467491440 S2P_Index_ST_48 0 "Normal" 1 "CSCNoSilent" 2 "CSCNoAnswer" 3 "NoLastCodeLine" 4 "CSCNumWrong" 5 "RelayClosedOrISysIsnotZero" 6 "MatchCodeWrong" 7 "CSCSAnswerIsNoChange" ;
VAL_ 2467491440 S2P_Index_Err_48 0 "Normal " 1 "No.1CSC " 2 "No.2 CSC" ;
VAL_ 2467491441 S2P_Index_ST_49 0 "Normal" 1 "CSCNoSilent" 2 "CSCNoAnswer" 3 "NoLastCodeLine" 4 "CSCNumWrong" 5 "RelayClosedOrISysIsnotZero" 6 "MatchCodeWrong" 7 "CSCSAnswerIsNoChange" ;
VAL_ 2467491441 S2P_Index_Err_49 0 "Normal " 1 "No.1CSC " 2 "No.2 CSC" ;
VAL_ 2467491442 S2P_Index_ST_50 0 "Normal" 1 "CSCNoSilent" 2 "CSCNoAnswer" 3 "NoLastCodeLine" 4 "CSCNumWrong" 5 "RelayClosedOrISysIsnotZero" 6 "MatchCodeWrong" 7 "CSCSAnswerIsNoChange" ;
VAL_ 2467491442 S2P_Index_Err_50 0 "Normal " 1 "No.1CSC " 2 "No.2 CSC" ;
VAL_ 2467491443 S2P_Index_ST_51 0 "Normal" 1 "CSCNoSilent" 2 "CSCNoAnswer" 3 "NoLastCodeLine" 4 "CSCNumWrong" 5 "RelayClosedOrISysIsnotZero" 6 "MatchCodeWrong" 7 "CSCSAnswerIsNoChange" ;
VAL_ 2467491443 S2P_Index_Err_51 0 "Normal " 1 "No.1CSC " 2 "No.2 CSC" ;
VAL_ 2467491444 S2P_Index_ST_52 0 "Normal" 1 "CSCNoSilent" 2 "CSCNoAnswer" 3 "NoLastCodeLine" 4 "CSCNumWrong" 5 "RelayClosedOrISysIsnotZero" 6 "MatchCodeWrong" 7 "CSCSAnswerIsNoChange" ;
VAL_ 2467491444 S2P_Index_Err_52 0 "Normal " 1 "No.1CSC " 2 "No.2 CSC" ;
VAL_ 2467491445 S2P_Index_ST_53 0 "Normal" 1 "CSCNoSilent" 2 "CSCNoAnswer" 3 "NoLastCodeLine" 4 "CSCNumWrong" 5 "RelayClosedOrISysIsnotZero" 6 "MatchCodeWrong" 7 "CSCSAnswerIsNoChange" ;
VAL_ 2467491445 S2P_Index_Err_53 0 "Normal " 1 "No.1CSC " 2 "No.2 CSC" ;
VAL_ 2467491446 S2P_Index_ST_54 0 "Normal" 1 "CSCNoSilent" 2 "CSCNoAnswer" 3 "NoLastCodeLine" 4 "CSCNumWrong" 5 "RelayClosedOrISysIsnotZero" 6 "MatchCodeWrong" 7 "CSCSAnswerIsNoChange" ;
VAL_ 2467491446 S2P_Index_Err_54 0 "Normal " 1 "No.1CSC " 2 "No.2 CSC" ;
VAL_ 2467491447 S2P_Index_ST_55 0 "Normal" 1 "CSCNoSilent" 2 "CSCNoAnswer" 3 "NoLastCodeLine" 4 "CSCNumWrong" 5 "RelayClosedOrISysIsnotZero" 6 "MatchCodeWrong" 7 "CSCSAnswerIsNoChange" ;
VAL_ 2467491447 S2P_Index_Err_55 0 "Normal " 1 "No.1CSC " 2 "No.2 CSC" ;
VAL_ 2467491448 S2P_Index_ST_56 0 "Normal" 1 "CSCNoSilent" 2 "CSCNoAnswer" 3 "NoLastCodeLine" 4 "CSCNumWrong" 5 "RelayClosedOrISysIsnotZero" 6 "MatchCodeWrong" 7 "CSCSAnswerIsNoChange" ;
VAL_ 2467491448 S2P_Index_Err_56 0 "Normal " 1 "No.1CSC " 2 "No.2 CSC" ;
VAL_ 2467491449 S2P_Index_ST_57 0 "Normal" 1 "CSCNoSilent" 2 "CSCNoAnswer" 3 "NoLastCodeLine" 4 "CSCNumWrong" 5 "RelayClosedOrISysIsnotZero" 6 "MatchCodeWrong" 7 "CSCSAnswerIsNoChange" ;
VAL_ 2467491449 S2P_Index_Err_57 0 "Normal " 1 "No.1CSC " 2 "No.2 CSC" ;
VAL_ 2467491450 S2P_Index_ST_58 0 "Normal" 1 "CSCNoSilent" 2 "CSCNoAnswer" 3 "NoLastCodeLine" 4 "CSCNumWrong" 5 "RelayClosedOrISysIsnotZero" 6 "MatchCodeWrong" 7 "CSCSAnswerIsNoChange" ;
VAL_ 2467491450 S2P_Index_Err_58 0 "Normal " 1 "No.1CSC " 2 "No.2 CSC" ;
VAL_ 2467491451 S2P_Index_ST_59 0 "Normal" 1 "CSCNoSilent" 2 "CSCNoAnswer" 3 "NoLastCodeLine" 4 "CSCNumWrong" 5 "RelayClosedOrISysIsnotZero" 6 "MatchCodeWrong" 7 "CSCSAnswerIsNoChange" ;
VAL_ 2467491451 S2P_Index_Err_59 0 "Normal " 1 "No.1CSC " 2 "No.2 CSC" ;
VAL_ 2467491452 S2P_Index_ST_60 0 "Normal" 1 "CSCNoSilent" 2 "CSCNoAnswer" 3 "NoLastCodeLine" 4 "CSCNumWrong" 5 "RelayClosedOrISysIsnotZero" 6 "MatchCodeWrong" 7 "CSCSAnswerIsNoChange" ;
VAL_ 2467491452 S2P_Index_Err_60 0 "Normal " 1 "No.1CSC " 2 "No.2 CSC" ;
VAL_ 2467491453 S2P_Index_ST_61 0 "Normal" 1 "CSCNoSilent" 2 "CSCNoAnswer" 3 "NoLastCodeLine" 4 "CSCNumWrong" 5 "RelayClosedOrISysIsnotZero" 6 "MatchCodeWrong" 7 "CSCSAnswerIsNoChange" ;
VAL_ 2467491453 S2P_Index_Err_61 0 "Normal " 1 "No.1CSC " 2 "No.2 CSC" ;
VAL_ 2467491454 S2P_Index_ST_62 0 "Normal" 1 "CSCNoSilent" 2 "CSCNoAnswer" 3 "NoLastCodeLine" 4 "CSCNumWrong" 5 "RelayClosedOrISysIsnotZero" 6 "MatchCodeWrong" 7 "CSCSAnswerIsNoChange" ;
VAL_ 2467491454 S2P_Index_Err_62 0 "Normal " 1 "No.1CSC " 2 "No.2 CSC" ;
VAL_ 2467491455 S2P_Index_ST_63 0 "Normal" 1 "CSCNoSilent" 2 "CSCNoAnswer" 3 "NoLastCodeLine" 4 "CSCNumWrong" 5 "RelayClosedOrISysIsnotZero" 6 "MatchCodeWrong" 7 "CSCSAnswerIsNoChange" ;
VAL_ 2467491455 S2P_Index_Err_63 0 "Normal " 1 "No.1CSC " 2 "No.2 CSC" ;
VAL_ 2400316993 CSC_U_No_01 1 "CSC 1" 2 "CSC 2" 3 "CSC 3" 4 "CSC 4" 5 "CSC 5" 6 "CSC 6" ;
VAL_ 2400316993 CSC_Ucell_01_01 65535 "Invalid" ;
VAL_ 2400316993 CSC_Ucell_02_01 65535 "Invalid" ;
VAL_ 2400316993 CSC_Ucell_03_01 65535 "Invalid" ;
VAL_ 2400316993 CSC_Ucell_04_01 65535 "Invalid" ;
VAL_ 2400316993 CSC_Ucell_05_01 65535 "Invalid" ;
VAL_ 2400316993 CSC_Ucell_06_01 65535 "Invalid" ;
VAL_ 2400316993 CSC_Ucell_07_01 65535 "Invalid" ;
VAL_ 2400316993 CSC_Ucell_08_01 65535 "Invalid" ;
VAL_ 2400316993 CSC_Ucell_09_01 65535 "Invalid" ;
VAL_ 2400316993 CSC_Ucell_10_01 65535 "Invalid" ;
VAL_ 2400316993 CSC_Ucell_11_01 65535 "Invalid" ;
VAL_ 2400316993 CSC_Ucell_12_01 65535 "Invalid" ;
VAL_ 2400316993 CSC_Ucell_13_01 65535 "Invalid" ;
VAL_ 2400316993 CSC_Ucell_14_01 65535 "Invalid" ;
VAL_ 2400316993 CSC_Ucell_15_01 65535 "Invalid" ;
VAL_ 2400316993 CSC_Ucell_16_01 65535 "Invalid" ;
VAL_ 2400316993 CSC_Ucell_17_01 65535 "Invalid" ;
VAL_ 2400316993 CSC_Ucell_18_01 65535 "Invalid" ;
VAL_ 2400316993 CSC_Ucell_19_01 65535 "Invalid" ;
VAL_ 2400316993 CSC_Ucell_20_01 65535 "Invalid" ;
VAL_ 2400316993 CSC_Ucell_21_01 65535 "Invalid" ;
VAL_ 2400316993 CSC_Ucell_22_01 65535 "Invalid" ;
VAL_ 2400316993 CSC_Ucell_23_01 65535 "Invalid" ;
VAL_ 2400316993 CSC_Ucell_24_01 65535 "Invalid" ;
VAL_ 2400316993 CSC_Ucell_25_01 65535 "Invalid" ;
VAL_ 2400316993 CSC_Ucell_26_01 65535 "Invalid" ;
VAL_ 2400316993 CSC_Ucell_27_01 65535 "Invalid" ;
VAL_ 2400316993 CSC_Ucell_28_01 65535 "Invalid" ;
VAL_ 2400316993 CSC_Ucell_29_01 65535 "Invalid" ;
VAL_ 2400316993 CSC_Ucell_30_01 65535 "Invalid" ;
VAL_ 2400316993 CSC_Ucell_31_01 65535 "Invalid" ;
VAL_ 2400316993 CSC_Ucell_32_01 65535 "Invalid" ;
VAL_ 2400316993 CSC_Ucell_33_01 65535 "Invalid" ;
VAL_ 2400316993 CSC_Ucell_34_01 65535 "Invalid" ;
VAL_ 2400316993 CSC_Ucell_35_01 65535 "Invalid" ;
VAL_ 2400316993 CSC_Ucell_36_01 65535 "Invalid" ;
VAL_ 2400316993 CSC_Ucell_37_01 65535 "Invalid" ;
VAL_ 2400316993 CSC_Ucell_38_01 65535 "Invalid" ;
VAL_ 2400316993 CSC_Ucell_39_01 65535 "Invalid" ;
VAL_ 2400316993 CSC_Ucell_40_01 65535 "Invalid" ;
VAL_ 2400316993 CSC_Ucell_41_01 65535 "Invalid" ;
VAL_ 2400316993 CSC_Ucell_42_01 65535 "Invalid" ;
VAL_ 2400316993 CSC_Ucell_43_01 65535 "Invalid" ;
VAL_ 2400316993 CSC_Ucell_44_01 65535 "Invalid" ;
VAL_ 2400316993 CSC_Ucell_45_01 65535 "Invalid" ;
VAL_ 2400316993 CSC_Ucell_46_01 65535 "Invalid" ;
VAL_ 2400316993 CSC_Ucell_47_01 65535 "Invalid" ;
VAL_ 2400316993 CSC_Ucell_48_01 65535 "Invalid" ;
VAL_ 2400316993 CSC_Ucell_49_01 65535 "Invalid" ;
VAL_ 2400316993 CSC_Ucell_50_01 65535 "Invalid" ;
VAL_ 2400316993 CSC_Ucell_51_01 65535 "Invalid" ;
VAL_ 2400316993 CSC_Ucell_52_01 65535 "Invalid" ;
VAL_ 2400316993 CSC_Ucell_53_01 65535 "Invalid" ;
VAL_ 2400316993 CSC_Ucell_54_01 65535 "Invalid" ;
VAL_ 2400316993 CSC_Ucell_55_01 65535 "Invalid" ;
VAL_ 2400316993 CSC_Ucell_56_01 65535 "Invalid" ;
VAL_ 2400316994 CSC_U_No_02 1 "CSC 1" 2 "CSC 2" 3 "CSC 3" 4 "CSC 4" 5 "CSC 5" 6 "CSC 6" ;
VAL_ 2400316994 CSC_Ucell_01_02 65535 "Invalid" ;
VAL_ 2400316994 CSC_Ucell_02_02 65535 "Invalid" ;
VAL_ 2400316994 CSC_Ucell_03_02 65535 "Invalid" ;
VAL_ 2400316994 CSC_Ucell_04_02 65535 "Invalid" ;
VAL_ 2400316994 CSC_Ucell_05_02 65535 "Invalid" ;
VAL_ 2400316994 CSC_Ucell_06_02 65535 "Invalid" ;
VAL_ 2400316994 CSC_Ucell_07_02 65535 "Invalid" ;
VAL_ 2400316994 CSC_Ucell_08_02 65535 "Invalid" ;
VAL_ 2400316994 CSC_Ucell_09_02 65535 "Invalid" ;
VAL_ 2400316994 CSC_Ucell_10_02 65535 "Invalid" ;
VAL_ 2400316994 CSC_Ucell_11_02 65535 "Invalid" ;
VAL_ 2400316994 CSC_Ucell_12_02 65535 "Invalid" ;
VAL_ 2400316994 CSC_Ucell_13_02 65535 "Invalid" ;
VAL_ 2400316994 CSC_Ucell_14_02 65535 "Invalid" ;
VAL_ 2400316994 CSC_Ucell_15_02 65535 "Invalid" ;
VAL_ 2400316994 CSC_Ucell_16_02 65535 "Invalid" ;
VAL_ 2400316994 CSC_Ucell_17_02 65535 "Invalid" ;
VAL_ 2400316994 CSC_Ucell_18_02 65535 "Invalid" ;
VAL_ 2400316994 CSC_Ucell_19_02 65535 "Invalid" ;
VAL_ 2400316994 CSC_Ucell_20_02 65535 "Invalid" ;
VAL_ 2400316994 CSC_Ucell_21_02 65535 "Invalid" ;
VAL_ 2400316994 CSC_Ucell_22_02 65535 "Invalid" ;
VAL_ 2400316994 CSC_Ucell_23_02 65535 "Invalid" ;
VAL_ 2400316994 CSC_Ucell_24_02 65535 "Invalid" ;
VAL_ 2400316994 CSC_Ucell_25_02 65535 "Invalid" ;
VAL_ 2400316994 CSC_Ucell_26_02 65535 "Invalid" ;
VAL_ 2400316994 CSC_Ucell_27_02 65535 "Invalid" ;
VAL_ 2400316994 CSC_Ucell_28_02 65535 "Invalid" ;
VAL_ 2400316994 CSC_Ucell_29_02 65535 "Invalid" ;
VAL_ 2400316994 CSC_Ucell_30_02 65535 "Invalid" ;
VAL_ 2400316994 CSC_Ucell_31_02 65535 "Invalid" ;
VAL_ 2400316994 CSC_Ucell_32_02 65535 "Invalid" ;
VAL_ 2400316994 CSC_Ucell_33_02 65535 "Invalid" ;
VAL_ 2400316994 CSC_Ucell_34_02 65535 "Invalid" ;
VAL_ 2400316994 CSC_Ucell_35_02 65535 "Invalid" ;
VAL_ 2400316994 CSC_Ucell_36_02 65535 "Invalid" ;
VAL_ 2400316994 CSC_Ucell_37_02 65535 "Invalid" ;
VAL_ 2400316994 CSC_Ucell_38_02 65535 "Invalid" ;
VAL_ 2400316994 CSC_Ucell_39_02 65535 "Invalid" ;
VAL_ 2400316994 CSC_Ucell_40_02 65535 "Invalid" ;
VAL_ 2400316994 CSC_Ucell_41_02 65535 "Invalid" ;
VAL_ 2400316994 CSC_Ucell_42_02 65535 "Invalid" ;
VAL_ 2400316994 CSC_Ucell_43_02 65535 "Invalid" ;
VAL_ 2400316994 CSC_Ucell_44_02 65535 "Invalid" ;
VAL_ 2400316994 CSC_Ucell_45_02 65535 "Invalid" ;
VAL_ 2400316994 CSC_Ucell_46_02 65535 "Invalid" ;
VAL_ 2400316994 CSC_Ucell_47_02 65535 "Invalid" ;
VAL_ 2400316994 CSC_Ucell_48_02 65535 "Invalid" ;
VAL_ 2400316994 CSC_Ucell_49_02 65535 "Invalid" ;
VAL_ 2400316994 CSC_Ucell_50_02 65535 "Invalid" ;
VAL_ 2400316994 CSC_Ucell_51_02 65535 "Invalid" ;
VAL_ 2400316994 CSC_Ucell_52_02 65535 "Invalid" ;
VAL_ 2400316994 CSC_Ucell_53_02 65535 "Invalid" ;
VAL_ 2400316994 CSC_Ucell_54_02 65535 "Invalid" ;
VAL_ 2400316994 CSC_Ucell_55_02 65535 "Invalid" ;
VAL_ 2400316994 CSC_Ucell_56_02 65535 "Invalid" ;
VAL_ 2400316995 CSC_U_No_03 1 "CSC 1" 2 "CSC 2" 3 "CSC 3" 4 "CSC 4" 5 "CSC 5" 6 "CSC 6" ;
VAL_ 2400316995 CSC_Ucell_01_03 65535 "Invalid" ;
VAL_ 2400316995 CSC_Ucell_02_03 65535 "Invalid" ;
VAL_ 2400316995 CSC_Ucell_03_03 65535 "Invalid" ;
VAL_ 2400316995 CSC_Ucell_04_03 65535 "Invalid" ;
VAL_ 2400316995 CSC_Ucell_05_03 65535 "Invalid" ;
VAL_ 2400316995 CSC_Ucell_06_03 65535 "Invalid" ;
VAL_ 2400316995 CSC_Ucell_07_03 65535 "Invalid" ;
VAL_ 2400316995 CSC_Ucell_08_03 65535 "Invalid" ;
VAL_ 2400316995 CSC_Ucell_09_03 65535 "Invalid" ;
VAL_ 2400316995 CSC_Ucell_10_03 65535 "Invalid" ;
VAL_ 2400316995 CSC_Ucell_11_03 65535 "Invalid" ;
VAL_ 2400316995 CSC_Ucell_12_03 65535 "Invalid" ;
VAL_ 2400316995 CSC_Ucell_13_03 65535 "Invalid" ;
VAL_ 2400316995 CSC_Ucell_14_03 65535 "Invalid" ;
VAL_ 2400316995 CSC_Ucell_15_03 65535 "Invalid" ;
VAL_ 2400316995 CSC_Ucell_16_03 65535 "Invalid" ;
VAL_ 2400316995 CSC_Ucell_17_03 65535 "Invalid" ;
VAL_ 2400316995 CSC_Ucell_18_03 65535 "Invalid" ;
VAL_ 2400316995 CSC_Ucell_19_03 65535 "Invalid" ;
VAL_ 2400316995 CSC_Ucell_20_03 65535 "Invalid" ;
VAL_ 2400316995 CSC_Ucell_21_03 65535 "Invalid" ;
VAL_ 2400316995 CSC_Ucell_22_03 65535 "Invalid" ;
VAL_ 2400316995 CSC_Ucell_23_03 65535 "Invalid" ;
VAL_ 2400316995 CSC_Ucell_24_03 65535 "Invalid" ;
VAL_ 2400316995 CSC_Ucell_25_03 65535 "Invalid" ;
VAL_ 2400316995 CSC_Ucell_26_03 65535 "Invalid" ;
VAL_ 2400316995 CSC_Ucell_27_03 65535 "Invalid" ;
VAL_ 2400316995 CSC_Ucell_28_03 65535 "Invalid" ;
VAL_ 2400316995 CSC_Ucell_29_03 65535 "Invalid" ;
VAL_ 2400316995 CSC_Ucell_30_03 65535 "Invalid" ;
VAL_ 2400316995 CSC_Ucell_31_03 65535 "Invalid" ;
VAL_ 2400316995 CSC_Ucell_32_03 65535 "Invalid" ;
VAL_ 2400316995 CSC_Ucell_33_03 65535 "Invalid" ;
VAL_ 2400316995 CSC_Ucell_34_03 65535 "Invalid" ;
VAL_ 2400316995 CSC_Ucell_35_03 65535 "Invalid" ;
VAL_ 2400316995 CSC_Ucell_36_03 65535 "Invalid" ;
VAL_ 2400316995 CSC_Ucell_37_03 65535 "Invalid" ;
VAL_ 2400316995 CSC_Ucell_38_03 65535 "Invalid" ;
VAL_ 2400316995 CSC_Ucell_39_03 65535 "Invalid" ;
VAL_ 2400316995 CSC_Ucell_40_03 65535 "Invalid" ;
VAL_ 2400316995 CSC_Ucell_41_03 65535 "Invalid" ;
VAL_ 2400316995 CSC_Ucell_42_03 65535 "Invalid" ;
VAL_ 2400316995 CSC_Ucell_43_03 65535 "Invalid" ;
VAL_ 2400316995 CSC_Ucell_44_03 65535 "Invalid" ;
VAL_ 2400316995 CSC_Ucell_45_03 65535 "Invalid" ;
VAL_ 2400316995 CSC_Ucell_46_03 65535 "Invalid" ;
VAL_ 2400316995 CSC_Ucell_47_03 65535 "Invalid" ;
VAL_ 2400316995 CSC_Ucell_48_03 65535 "Invalid" ;
VAL_ 2400316995 CSC_Ucell_49_03 65535 "Invalid" ;
VAL_ 2400316995 CSC_Ucell_50_03 65535 "Invalid" ;
VAL_ 2400316995 CSC_Ucell_51_03 65535 "Invalid" ;
VAL_ 2400316995 CSC_Ucell_52_03 65535 "Invalid" ;
VAL_ 2400316995 CSC_Ucell_53_03 65535 "Invalid" ;
VAL_ 2400316995 CSC_Ucell_54_03 65535 "Invalid" ;
VAL_ 2400316995 CSC_Ucell_55_03 65535 "Invalid" ;
VAL_ 2400316995 CSC_Ucell_56_03 65535 "Invalid" ;
VAL_ 2400316996 CSC_U_No_04 1 "CSC 1" 2 "CSC 2" 3 "CSC 3" 4 "CSC 4" 5 "CSC 5" 6 "CSC 6" ;
VAL_ 2400316996 CSC_Ucell_01_04 65535 "Invalid" ;
VAL_ 2400316996 CSC_Ucell_02_04 65535 "Invalid" ;
VAL_ 2400316996 CSC_Ucell_03_04 65535 "Invalid" ;
VAL_ 2400316996 CSC_Ucell_04_04 65535 "Invalid" ;
VAL_ 2400316996 CSC_Ucell_05_04 65535 "Invalid" ;
VAL_ 2400316996 CSC_Ucell_06_04 65535 "Invalid" ;
VAL_ 2400316996 CSC_Ucell_07_04 65535 "Invalid" ;
VAL_ 2400316996 CSC_Ucell_08_04 65535 "Invalid" ;
VAL_ 2400316996 CSC_Ucell_09_04 65535 "Invalid" ;
VAL_ 2400316996 CSC_Ucell_10_04 65535 "Invalid" ;
VAL_ 2400316996 CSC_Ucell_11_04 65535 "Invalid" ;
VAL_ 2400316996 CSC_Ucell_12_04 65535 "Invalid" ;
VAL_ 2400316996 CSC_Ucell_13_04 65535 "Invalid" ;
VAL_ 2400316996 CSC_Ucell_14_04 65535 "Invalid" ;
VAL_ 2400316996 CSC_Ucell_15_04 65535 "Invalid" ;
VAL_ 2400316996 CSC_Ucell_16_04 65535 "Invalid" ;
VAL_ 2400316996 CSC_Ucell_17_04 65535 "Invalid" ;
VAL_ 2400316996 CSC_Ucell_18_04 65535 "Invalid" ;
VAL_ 2400316996 CSC_Ucell_19_04 65535 "Invalid" ;
VAL_ 2400316996 CSC_Ucell_20_04 65535 "Invalid" ;
VAL_ 2400316996 CSC_Ucell_21_04 65535 "Invalid" ;
VAL_ 2400316996 CSC_Ucell_22_04 65535 "Invalid" ;
VAL_ 2400316996 CSC_Ucell_23_04 65535 "Invalid" ;
VAL_ 2400316996 CSC_Ucell_24_04 65535 "Invalid" ;
VAL_ 2400316996 CSC_Ucell_25_04 65535 "Invalid" ;
VAL_ 2400316996 CSC_Ucell_26_04 65535 "Invalid" ;
VAL_ 2400316996 CSC_Ucell_27_04 65535 "Invalid" ;
VAL_ 2400316996 CSC_Ucell_28_04 65535 "Invalid" ;
VAL_ 2400316996 CSC_Ucell_29_04 65535 "Invalid" ;
VAL_ 2400316996 CSC_Ucell_30_04 65535 "Invalid" ;
VAL_ 2400316996 CSC_Ucell_31_04 65535 "Invalid" ;
VAL_ 2400316996 CSC_Ucell_32_04 65535 "Invalid" ;
VAL_ 2400316996 CSC_Ucell_33_04 65535 "Invalid" ;
VAL_ 2400316996 CSC_Ucell_34_04 65535 "Invalid" ;
VAL_ 2400316996 CSC_Ucell_35_04 65535 "Invalid" ;
VAL_ 2400316996 CSC_Ucell_36_04 65535 "Invalid" ;
VAL_ 2400316996 CSC_Ucell_37_04 65535 "Invalid" ;
VAL_ 2400316996 CSC_Ucell_38_04 65535 "Invalid" ;
VAL_ 2400316996 CSC_Ucell_39_04 65535 "Invalid" ;
VAL_ 2400316996 CSC_Ucell_40_04 65535 "Invalid" ;
VAL_ 2400316996 CSC_Ucell_41_04 65535 "Invalid" ;
VAL_ 2400316996 CSC_Ucell_42_04 65535 "Invalid" ;
VAL_ 2400316996 CSC_Ucell_43_04 65535 "Invalid" ;
VAL_ 2400316996 CSC_Ucell_44_04 65535 "Invalid" ;
VAL_ 2400316996 CSC_Ucell_45_04 65535 "Invalid" ;
VAL_ 2400316996 CSC_Ucell_46_04 65535 "Invalid" ;
VAL_ 2400316996 CSC_Ucell_47_04 65535 "Invalid" ;
VAL_ 2400316996 CSC_Ucell_48_04 65535 "Invalid" ;
VAL_ 2400316996 CSC_Ucell_49_04 65535 "Invalid" ;
VAL_ 2400316996 CSC_Ucell_50_04 65535 "Invalid" ;
VAL_ 2400316996 CSC_Ucell_51_04 65535 "Invalid" ;
VAL_ 2400316996 CSC_Ucell_52_04 65535 "Invalid" ;
VAL_ 2400316996 CSC_Ucell_53_04 65535 "Invalid" ;
VAL_ 2400316996 CSC_Ucell_54_04 65535 "Invalid" ;
VAL_ 2400316996 CSC_Ucell_55_04 65535 "Invalid" ;
VAL_ 2400316996 CSC_Ucell_56_04 65535 "Invalid" ;
VAL_ 2400316997 CSC_U_No_05 1 "CSC 1" 2 "CSC 2" 3 "CSC 3" 4 "CSC 4" 5 "CSC 5" 6 "CSC 6" ;
VAL_ 2400316997 CSC_Ucell_01_05 65535 "Invalid" ;
VAL_ 2400316997 CSC_Ucell_02_05 65535 "Invalid" ;
VAL_ 2400316997 CSC_Ucell_03_05 65535 "Invalid" ;
VAL_ 2400316997 CSC_Ucell_04_05 65535 "Invalid" ;
VAL_ 2400316997 CSC_Ucell_05_05 65535 "Invalid" ;
VAL_ 2400316997 CSC_Ucell_06_05 65535 "Invalid" ;
VAL_ 2400316997 CSC_Ucell_07_05 65535 "Invalid" ;
VAL_ 2400316997 CSC_Ucell_08_05 65535 "Invalid" ;
VAL_ 2400316997 CSC_Ucell_09_05 65535 "Invalid" ;
VAL_ 2400316997 CSC_Ucell_10_05 65535 "Invalid" ;
VAL_ 2400316997 CSC_Ucell_11_05 65535 "Invalid" ;
VAL_ 2400316997 CSC_Ucell_12_05 65535 "Invalid" ;
VAL_ 2400316997 CSC_Ucell_13_05 65535 "Invalid" ;
VAL_ 2400316997 CSC_Ucell_14_05 65535 "Invalid" ;
VAL_ 2400316997 CSC_Ucell_15_05 65535 "Invalid" ;
VAL_ 2400316997 CSC_Ucell_16_05 65535 "Invalid" ;
VAL_ 2400316997 CSC_Ucell_17_05 65535 "Invalid" ;
VAL_ 2400316997 CSC_Ucell_18_05 65535 "Invalid" ;
VAL_ 2400316997 CSC_Ucell_19_05 65535 "Invalid" ;
VAL_ 2400316997 CSC_Ucell_20_05 65535 "Invalid" ;
VAL_ 2400316997 CSC_Ucell_21_05 65535 "Invalid" ;
VAL_ 2400316997 CSC_Ucell_22_05 65535 "Invalid" ;
VAL_ 2400316997 CSC_Ucell_23_05 65535 "Invalid" ;
VAL_ 2400316997 CSC_Ucell_24_05 65535 "Invalid" ;
VAL_ 2400316997 CSC_Ucell_25_05 65535 "Invalid" ;
VAL_ 2400316997 CSC_Ucell_26_05 65535 "Invalid" ;
VAL_ 2400316997 CSC_Ucell_27_05 65535 "Invalid" ;
VAL_ 2400316997 CSC_Ucell_28_05 65535 "Invalid" ;
VAL_ 2400316997 CSC_Ucell_29_05 65535 "Invalid" ;
VAL_ 2400316997 CSC_Ucell_30_05 65535 "Invalid" ;
VAL_ 2400316997 CSC_Ucell_31_05 65535 "Invalid" ;
VAL_ 2400316997 CSC_Ucell_32_05 65535 "Invalid" ;
VAL_ 2400316997 CSC_Ucell_33_05 65535 "Invalid" ;
VAL_ 2400316997 CSC_Ucell_34_05 65535 "Invalid" ;
VAL_ 2400316997 CSC_Ucell_35_05 65535 "Invalid" ;
VAL_ 2400316997 CSC_Ucell_36_05 65535 "Invalid" ;
VAL_ 2400316997 CSC_Ucell_37_05 65535 "Invalid" ;
VAL_ 2400316997 CSC_Ucell_38_05 65535 "Invalid" ;
VAL_ 2400316997 CSC_Ucell_39_05 65535 "Invalid" ;
VAL_ 2400316997 CSC_Ucell_40_05 65535 "Invalid" ;
VAL_ 2400316997 CSC_Ucell_41_05 65535 "Invalid" ;
VAL_ 2400316997 CSC_Ucell_42_05 65535 "Invalid" ;
VAL_ 2400316997 CSC_Ucell_43_05 65535 "Invalid" ;
VAL_ 2400316997 CSC_Ucell_44_05 65535 "Invalid" ;
VAL_ 2400316997 CSC_Ucell_45_05 65535 "Invalid" ;
VAL_ 2400316997 CSC_Ucell_46_05 65535 "Invalid" ;
VAL_ 2400316997 CSC_Ucell_47_05 65535 "Invalid" ;
VAL_ 2400316997 CSC_Ucell_48_05 65535 "Invalid" ;
VAL_ 2400316997 CSC_Ucell_49_05 65535 "Invalid" ;
VAL_ 2400316997 CSC_Ucell_50_05 65535 "Invalid" ;
VAL_ 2400316997 CSC_Ucell_51_05 65535 "Invalid" ;
VAL_ 2400316997 CSC_Ucell_52_05 65535 "Invalid" ;
VAL_ 2400316997 CSC_Ucell_53_05 65535 "Invalid" ;
VAL_ 2400316997 CSC_Ucell_54_05 65535 "Invalid" ;
VAL_ 2400316997 CSC_Ucell_55_05 65535 "Invalid" ;
VAL_ 2400316997 CSC_Ucell_56_05 65535 "Invalid" ;
VAL_ 2400316998 CSC_U_No_06 1 "CSC 1" 2 "CSC 2" 3 "CSC 3" 4 "CSC 4" 5 "CSC 5" 6 "CSC 6" ;
VAL_ 2400316998 CSC_Ucell_01_06 65535 "Invalid" ;
VAL_ 2400316998 CSC_Ucell_02_06 65535 "Invalid" ;
VAL_ 2400316998 CSC_Ucell_03_06 65535 "Invalid" ;
VAL_ 2400316998 CSC_Ucell_04_06 65535 "Invalid" ;
VAL_ 2400316998 CSC_Ucell_05_06 65535 "Invalid" ;
VAL_ 2400316998 CSC_Ucell_06_06 65535 "Invalid" ;
VAL_ 2400316998 CSC_Ucell_07_06 65535 "Invalid" ;
VAL_ 2400316998 CSC_Ucell_08_06 65535 "Invalid" ;
VAL_ 2400316998 CSC_Ucell_09_06 65535 "Invalid" ;
VAL_ 2400316998 CSC_Ucell_10_06 65535 "Invalid" ;
VAL_ 2400316998 CSC_Ucell_11_06 65535 "Invalid" ;
VAL_ 2400316998 CSC_Ucell_12_06 65535 "Invalid" ;
VAL_ 2400316998 CSC_Ucell_13_06 65535 "Invalid" ;
VAL_ 2400316998 CSC_Ucell_14_06 65535 "Invalid" ;
VAL_ 2400316998 CSC_Ucell_15_06 65535 "Invalid" ;
VAL_ 2400316998 CSC_Ucell_16_06 65535 "Invalid" ;
VAL_ 2400316998 CSC_Ucell_17_06 65535 "Invalid" ;
VAL_ 2400316998 CSC_Ucell_18_06 65535 "Invalid" ;
VAL_ 2400316998 CSC_Ucell_19_06 65535 "Invalid" ;
VAL_ 2400316998 CSC_Ucell_20_06 65535 "Invalid" ;
VAL_ 2400316998 CSC_Ucell_21_06 65535 "Invalid" ;
VAL_ 2400316998 CSC_Ucell_22_06 65535 "Invalid" ;
VAL_ 2400316998 CSC_Ucell_23_06 65535 "Invalid" ;
VAL_ 2400316998 CSC_Ucell_24_06 65535 "Invalid" ;
VAL_ 2400316998 CSC_Ucell_25_06 65535 "Invalid" ;
VAL_ 2400316998 CSC_Ucell_26_06 65535 "Invalid" ;
VAL_ 2400316998 CSC_Ucell_27_06 65535 "Invalid" ;
VAL_ 2400316998 CSC_Ucell_28_06 65535 "Invalid" ;
VAL_ 2400316998 CSC_Ucell_29_06 65535 "Invalid" ;
VAL_ 2400316998 CSC_Ucell_30_06 65535 "Invalid" ;
VAL_ 2400316998 CSC_Ucell_31_06 65535 "Invalid" ;
VAL_ 2400316998 CSC_Ucell_32_06 65535 "Invalid" ;
VAL_ 2400316998 CSC_Ucell_33_06 65535 "Invalid" ;
VAL_ 2400316998 CSC_Ucell_34_06 65535 "Invalid" ;
VAL_ 2400316998 CSC_Ucell_35_06 65535 "Invalid" ;
VAL_ 2400316998 CSC_Ucell_36_06 65535 "Invalid" ;
VAL_ 2400316998 CSC_Ucell_37_06 65535 "Invalid" ;
VAL_ 2400316998 CSC_Ucell_38_06 65535 "Invalid" ;
VAL_ 2400316998 CSC_Ucell_39_06 65535 "Invalid" ;
VAL_ 2400316998 CSC_Ucell_40_06 65535 "Invalid" ;
VAL_ 2400316998 CSC_Ucell_41_06 65535 "Invalid" ;
VAL_ 2400316998 CSC_Ucell_42_06 65535 "Invalid" ;
VAL_ 2400316998 CSC_Ucell_43_06 65535 "Invalid" ;
VAL_ 2400316998 CSC_Ucell_44_06 65535 "Invalid" ;
VAL_ 2400316998 CSC_Ucell_45_06 65535 "Invalid" ;
VAL_ 2400316998 CSC_Ucell_46_06 65535 "Invalid" ;
VAL_ 2400316998 CSC_Ucell_47_06 65535 "Invalid" ;
VAL_ 2400316998 CSC_Ucell_48_06 65535 "Invalid" ;
VAL_ 2400316998 CSC_Ucell_49_06 65535 "Invalid" ;
VAL_ 2400316998 CSC_Ucell_50_06 65535 "Invalid" ;
VAL_ 2400316998 CSC_Ucell_51_06 65535 "Invalid" ;
VAL_ 2400316998 CSC_Ucell_52_06 65535 "Invalid" ;
VAL_ 2400316998 CSC_Ucell_53_06 65535 "Invalid" ;
VAL_ 2400316998 CSC_Ucell_54_06 65535 "Invalid" ;
VAL_ 2400316998 CSC_Ucell_55_06 65535 "Invalid" ;
VAL_ 2400316998 CSC_Ucell_56_06 65535 "Invalid" ;
VAL_ 2400316999 CSC_U_No_07 1 "CSC 1" 2 "CSC 2" 3 "CSC 3" 4 "CSC 4" 5 "CSC 5" 6 "CSC 6" ;
VAL_ 2400316999 CSC_Ucell_01_07 65535 "Invalid" ;
VAL_ 2400316999 CSC_Ucell_02_07 65535 "Invalid" ;
VAL_ 2400316999 CSC_Ucell_03_07 65535 "Invalid" ;
VAL_ 2400316999 CSC_Ucell_04_07 65535 "Invalid" ;
VAL_ 2400316999 CSC_Ucell_05_07 65535 "Invalid" ;
VAL_ 2400316999 CSC_Ucell_06_07 65535 "Invalid" ;
VAL_ 2400316999 CSC_Ucell_07_07 65535 "Invalid" ;
VAL_ 2400316999 CSC_Ucell_08_07 65535 "Invalid" ;
VAL_ 2400316999 CSC_Ucell_09_07 65535 "Invalid" ;
VAL_ 2400316999 CSC_Ucell_10_07 65535 "Invalid" ;
VAL_ 2400316999 CSC_Ucell_11_07 65535 "Invalid" ;
VAL_ 2400316999 CSC_Ucell_12_07 65535 "Invalid" ;
VAL_ 2400316999 CSC_Ucell_13_07 65535 "Invalid" ;
VAL_ 2400316999 CSC_Ucell_14_07 65535 "Invalid" ;
VAL_ 2400316999 CSC_Ucell_15_07 65535 "Invalid" ;
VAL_ 2400316999 CSC_Ucell_16_07 65535 "Invalid" ;
VAL_ 2400316999 CSC_Ucell_17_07 65535 "Invalid" ;
VAL_ 2400316999 CSC_Ucell_18_07 65535 "Invalid" ;
VAL_ 2400316999 CSC_Ucell_19_07 65535 "Invalid" ;
VAL_ 2400316999 CSC_Ucell_20_07 65535 "Invalid" ;
VAL_ 2400316999 CSC_Ucell_21_07 65535 "Invalid" ;
VAL_ 2400316999 CSC_Ucell_22_07 65535 "Invalid" ;
VAL_ 2400316999 CSC_Ucell_23_07 65535 "Invalid" ;
VAL_ 2400316999 CSC_Ucell_24_07 65535 "Invalid" ;
VAL_ 2400316999 CSC_Ucell_25_07 65535 "Invalid" ;
VAL_ 2400316999 CSC_Ucell_26_07 65535 "Invalid" ;
VAL_ 2400316999 CSC_Ucell_27_07 65535 "Invalid" ;
VAL_ 2400316999 CSC_Ucell_28_07 65535 "Invalid" ;
VAL_ 2400316999 CSC_Ucell_29_07 65535 "Invalid" ;
VAL_ 2400316999 CSC_Ucell_30_07 65535 "Invalid" ;
VAL_ 2400316999 CSC_Ucell_31_07 65535 "Invalid" ;
VAL_ 2400316999 CSC_Ucell_32_07 65535 "Invalid" ;
VAL_ 2400316999 CSC_Ucell_33_07 65535 "Invalid" ;
VAL_ 2400316999 CSC_Ucell_34_07 65535 "Invalid" ;
VAL_ 2400316999 CSC_Ucell_35_07 65535 "Invalid" ;
VAL_ 2400316999 CSC_Ucell_36_07 65535 "Invalid" ;
VAL_ 2400316999 CSC_Ucell_37_07 65535 "Invalid" ;
VAL_ 2400316999 CSC_Ucell_38_07 65535 "Invalid" ;
VAL_ 2400316999 CSC_Ucell_39_07 65535 "Invalid" ;
VAL_ 2400316999 CSC_Ucell_40_07 65535 "Invalid" ;
VAL_ 2400316999 CSC_Ucell_41_07 65535 "Invalid" ;
VAL_ 2400316999 CSC_Ucell_42_07 65535 "Invalid" ;
VAL_ 2400316999 CSC_Ucell_43_07 65535 "Invalid" ;
VAL_ 2400316999 CSC_Ucell_44_07 65535 "Invalid" ;
VAL_ 2400316999 CSC_Ucell_45_07 65535 "Invalid" ;
VAL_ 2400316999 CSC_Ucell_46_07 65535 "Invalid" ;
VAL_ 2400316999 CSC_Ucell_47_07 65535 "Invalid" ;
VAL_ 2400316999 CSC_Ucell_48_07 65535 "Invalid" ;
VAL_ 2400316999 CSC_Ucell_49_07 65535 "Invalid" ;
VAL_ 2400316999 CSC_Ucell_50_07 65535 "Invalid" ;
VAL_ 2400316999 CSC_Ucell_51_07 65535 "Invalid" ;
VAL_ 2400316999 CSC_Ucell_52_07 65535 "Invalid" ;
VAL_ 2400316999 CSC_Ucell_53_07 65535 "Invalid" ;
VAL_ 2400316999 CSC_Ucell_54_07 65535 "Invalid" ;
VAL_ 2400316999 CSC_Ucell_55_07 65535 "Invalid" ;
VAL_ 2400316999 CSC_Ucell_56_07 65535 "Invalid" ;
VERSION ""

NS_ :

BS_:

BU_: MBMU PC SBMU IMM ETH DCDC LEMS

BO_ 2400382583 S2P_Detail_Tcell1__55: 8 SBMU
 SG_ CSC_T_No_55 : 0|8@1+ (1,0) [0|255] ""  PC
 SG_ CSC_Tcell_Frame_Index_55 M : 8|8@1+ (1,0) [0|255] ""  PC
 SG_ CSC_Tcell_01_55 m0 : 16|8@1+ (1,-50) [-50|205] "℃"  PC
 SG_ CSC_Tcell_02_55 m0 : 24|8@1+ (1,-50) [-50|205] "℃"  PC
 SG_ CSC_Tcell_03_55 m0 : 32|8@1+ (1,-50) [-50|205] "℃"  PC
 SG_ CSC_Tcell_04_55 m0 : 40|8@1+ (1,-50) [-50|205] "℃"  PC
 SG_ CSC_Tcell_05_55 m0 : 48|8@1+ (1,-50) [-50|205] "℃"  PC
 SG_ CSC_Tcell_06_55 m0 : 56|8@1+ (1,-50) [-50|205] "℃"  PC
 SG_ CSC_Tcell_07_55 m1 : 16|8@1+ (1,-50) [-50|205] "℃"  PC
 SG_ CSC_Tcell_08_55 m1 : 24|8@1+ (1,-50) [-50|205] "℃"  PC
 SG_ CSC_Tcell_09_55 m1 : 32|8@1+ (1,-50) [-50|205] "℃"  PC
 SG_ CSC_Tcell_10_55 m1 : 40|8@1+ (1,-50) [-50|205] "℃"  PC
 SG_ CSC_Tcell_11_55 m1 : 48|8@1+ (1,-50) [-50|205] "℃"  PC
 SG_ CSC_Tcell_12_55 m1 : 56|8@1+ (1,-50) [-50|205] "℃"  PC
 SG_ CSC_Tcell_13_55 m2 : 16|8@1+ (1,-50) [-50|205] "℃"  PC
 SG_ CSC_Tcell_14_55 m2 : 24|8@1+ (1,-50) [-50|205] "℃"  PC
 SG_ CSC_Tcell_15_55 m2 : 32|8@1+ (1,-50) [-50|205] "℃"  PC
 SG_ CSC_Tcell_16_55 m2 : 40|8@1+ (1,-50) [-50|205] "℃"  PC
 SG_ CSC_Tcell_17_55 m2 : 48|8@1+ (1,-50) [-50|205] "℃"  PC
 SG_ CSC_Tcell_18_55 m2 : 56|8@1+ (1,-50) [-50|205] "℃"  PC
 SG_ CSC_Tcell_19_55 m3 : 16|8@1+ (1,-50) [-50|205] "℃"  PC
 SG_ CSC_Tcell_20_55 m3 : 24|8@1+ (1,-50) [-50|205] "℃"  PC
 SG_ CSC_Tcell_21_55 m3 : 32|8@1+ (1,-50) [-50|205] "℃"  PC
 SG_ CSC_Tcell_22_55 m3 : 40|8@1+ (1,-50) [-50|205] "℃"  PC
 SG_ CSC_Tcell_23_55 m3 : 48|8@1+ (1,-50) [-50|205] "℃"  PC
 SG_ CSC_Tcell_24_55 m3 : 56|8@1+ (1,-50) [-50|205] "℃"  PC
 SG_ CSC_Tcell_25_55 m4 : 16|8@1+ (1,-50) [-50|205] "℃"  PC
 SG_ CSC_Tcell_26_55 m4 : 24|8@1+ (1,-50) [-50|205] "℃"  PC
 SG_ CSC_Tcell_27_55 m4 : 32|8@1+ (1,-50) [-50|205] "℃"  PC
 SG_ CSC_Tcell_28_55 m4 : 40|8@1+ (1,-50) [-50|205] "℃"  PC
 SG_ CSC_Tcell_29_55 m4 : 48|8@1+ (1,-50) [-50|205] "℃"  PC
 SG_ CSC_Tcell_30_55 m4 : 56|8@1+ (1,-50) [-50|205] "℃"  PC
 SG_ CSC_Tcell_31_55 m5 : 16|8@1+ (1,-50) [-50|205] "℃"  PC
 SG_ CSC_Tcell_32_55 m5 : 24|8@1+ (1,-50) [-50|205] "℃"  PC
 SG_ CSC_Tcell_33_55 m5 : 32|8@1+ (1,-50) [-50|205] "℃"  PC
 SG_ CSC_Tcell_34_55 m5 : 40|8@1+ (1,-50) [-50|205] "℃"  PC
 SG_ CSC_Tcell_35_55 m5 : 48|8@1+ (1,-50) [-50|205] "℃"  PC
 SG_ CSC_Tcell_36_55 m5 : 56|8@1+ (1,-50) [-50|205] "℃"  PC
 SG_ CSC_Tcell_37_55 m6 : 16|8@1+ (1,-50) [-50|205] "℃"  PC
 SG_ CSC_Tcell_38_55 m6 : 24|8@1+ (1,-50) [-50|205] "℃"  PC
 SG_ CSC_Tcell_39_55 m6 : 32|8@1+ (1,-50) [-50|205] "℃"  PC
 SG_ CSC_Tcell_40_55 m6 : 40|8@1+ (1,-50) [-50|205] "℃"  PC
 SG_ CSC_Tcell_41_55 m6 : 48|8@1+ (1,-50) [-50|205] "℃"  PC
 SG_ CSC_Tcell_42_55 m6 : 56|8@1+ (1,-50) [-50|205] "℃"  PC
 SG_ CSC_Tcell_43_55 m7 : 16|8@1+ (1,-50) [-50|205] "℃"  PC
 SG_ CSC_Tcell_44_55 m7 : 24|8@1+ (1,-50) [-50|205] "℃"  PC
 SG_ CSC_Tcell_45_55 m7 : 32|8@1+ (1,-50) [-50|205] "℃"  PC
 SG_ CSC_Tcell_46_55 m7 : 40|8@1+ (1,-50) [-50|205] "℃"  PC
 SG_ CSC_Tcell_47_55 m7 : 48|8@1+ (1,-50) [-50|205] "℃"  PC
 SG_ CSC_Tcell_48_55 m7 : 56|8@1+ (1,-50) [-50|205] "℃"  PC
 SG_ CSC_Tcell_49_55 m8 : 16|8@1+ (1,-50) [-50|205] "℃"  PC
 SG_ CSC_Tcell_50_55 m8 : 24|8@1+ (1,-50) [-50|205] "℃"  PC
 SG_ CSC_Tcell_51_55 m8 : 32|8@1+ (1,-50) [-50|205] "℃"  PC
 SG_ CSC_Tcell_52_55 m8 : 40|8@1+ (1,-50) [-50|205] "℃"  PC
 SG_ CSC_Tcell_53_55 m8 : 48|8@1+ (1,-50) [-50|205] "℃"  PC
 SG_ CSC_Tcell_54_55 m8 : 56|8@1+ (1,-50) [-50|205] "℃"  PC
 SG_ CSC_Tcell_55_55 m9 : 16|8@1+ (1,-50) [-50|205] "℃"  PC
 SG_ CSC_Tcell_56_55 m9 : 24|8@1+ (1,-50) [-50|205] "℃"  PC
 SG_ CSC_Tcell_57_55 m9 : 32|8@1+ (1,-50) [-50|205] "℃"  PC
 SG_ CSC_Tcell_58_55 m9 : 40|8@1+ (1,-50) [-50|205] "℃"  PC
 SG_ CSC_Tcell_59_55 m9 : 48|8@1+ (1,-50) [-50|205] "℃"  PC
 SG_ CSC_Tcell_60_55 m9 : 56|8@1+ (1,-50) [-50|205] "℃"  PC
 SG_ CSC_Tcell_61_55 m10 : 16|8@1+ (1,-50) [-50|205] "℃"  PC
 SG_ CSC_Tcell_62_55 m10 : 24|8@1+ (1,-50) [-50|205] "℃"  PC
 SG_ CSC_Tcell_63_55 m10 : 32|8@1+ (1,-50) [-50|205] "℃"  PC
 SG_ CSC_Tcell_64_55 m10 : 40|8@1+ (1,-50) [-50|205] "℃"  PC
 SG_ CSC_Tcell_65_55 m10 : 48|8@1+ (1,-50) [-50|205] "℃"  PC
 SG_ CSC_Tcell_66_55 m10 : 56|8@1+ (1,-50) [-50|205] "℃"  PC
 SG_ CSC_Tcell_67_55 m11 : 16|8@1+ (1,-50) [-50|205] "℃"  PC
 SG_ CSC_Tcell_68_55 m11 : 24|8@1+ (1,-50) [-50|205] "℃"  PC
 SG_ CSC_Tcell_69_55 m11 : 32|8@1+ (1,-50) [-50|205] "℃"  PC
 SG_ CSC_Tcell_70_55 m11 : 40|8@1+ (1,-50) [-50|205] "℃"  PC
 SG_ CSC_Tcell_71_55 m11 : 48|8@1+ (1,-50) [-50|205] "℃"  PC
 SG_ CSC_Tcell_72_55 m11 : 56|8@1+ (1,-50) [-50|205] "℃"  PC

BO_ 2400382584 S2P_Detail_Tcell1__56: 8 SBMU
 SG_ CSC_T_No_56 : 0|8@1+ (1,0) [0|255] ""  PC
 SG_ CSC_Tcell_Frame_Index_56 M : 8|8@1+ (1,0) [0|255] ""  PC
 SG_ CSC_Tcell_01_56 m0 : 16|8@1+ (1,-50) [-50|205] "℃"  PC
 SG_ CSC_Tcell_02_56 m0 : 24|8@1+ (1,-50) [-50|205] "℃"  PC
 SG_ CSC_Tcell_03_56 m0 : 32|8@1+ (1,-50) [-50|205] "℃"  PC
 SG_ CSC_Tcell_04_56 m0 : 40|8@1+ (1,-50) [-50|205] "℃"  PC
 SG_ CSC_Tcell_05_56 m0 : 48|8@1+ (1,-50) [-50|205] "℃"  PC
 SG_ CSC_Tcell_06_56 m0 : 56|8@1+ (1,-50) [-50|205] "℃"  PC
 SG_ CSC_Tcell_07_56 m1 : 16|8@1+ (1,-50) [-50|205] "℃"  PC
 SG_ CSC_Tcell_08_56 m1 : 24|8@1+ (1,-50) [-50|205] "℃"  PC
 SG_ CSC_Tcell_09_56 m1 : 32|8@1+ (1,-50) [-50|205] "℃"  PC
 SG_ CSC_Tcell_10_56 m1 : 40|8@1+ (1,-50) [-50|205] "℃"  PC
 SG_ CSC_Tcell_11_56 m1 : 48|8@1+ (1,-50) [-50|205] "℃"  PC
 SG_ CSC_Tcell_12_56 m1 : 56|8@1+ (1,-50) [-50|205] "℃"  PC
 SG_ CSC_Tcell_13_56 m2 : 16|8@1+ (1,-50) [-50|205] "℃"  PC
 SG_ CSC_Tcell_14_56 m2 : 24|8@1+ (1,-50) [-50|205] "℃"  PC
 SG_ CSC_Tcell_15_56 m2 : 32|8@1+ (1,-50) [-50|205] "℃"  PC
 SG_ CSC_Tcell_16_56 m2 : 40|8@1+ (1,-50) [-50|205] "℃"  PC
 SG_ CSC_Tcell_17_56 m2 : 48|8@1+ (1,-50) [-50|205] "℃"  PC
 SG_ CSC_Tcell_18_56 m2 : 56|8@1+ (1,-50) [-50|205] "℃"  PC
 SG_ CSC_Tcell_19_56 m3 : 16|8@1+ (1,-50) [-50|205] "℃"  PC
 SG_ CSC_Tcell_20_56 m3 : 24|8@1+ (1,-50) [-50|205] "℃"  PC
 SG_ CSC_Tcell_21_56 m3 : 32|8@1+ (1,-50) [-50|205] "℃"  PC
 SG_ CSC_Tcell_22_56 m3 : 40|8@1+ (1,-50) [-50|205] "℃"  PC
 SG_ CSC_Tcell_23_56 m3 : 48|8@1+ (1,-50) [-50|205] "℃"  PC
 SG_ CSC_Tcell_24_56 m3 : 56|8@1+ (1,-50) [-50|205] "℃"  PC
 SG_ CSC_Tcell_25_56 m4 : 16|8@1+ (1,-50) [-50|205] "℃"  PC
 SG_ CSC_Tcell_26_56 m4 : 24|8@1+ (1,-50) [-50|205] "℃"  PC
 SG_ CSC_Tcell_27_56 m4 : 32|8@1+ (1,-50) [-50|205] "℃"  PC
 SG_ CSC_Tcell_28_56 m4 : 40|8@1+ (1,-50) [-50|205] "℃"  PC
 SG_ CSC_Tcell_29_56 m4 : 48|8@1+ (1,-50) [-50|205] "℃"  PC
 SG_ CSC_Tcell_30_56 m4 : 56|8@1+ (1,-50) [-50|205] "℃"  PC
 SG_ CSC_Tcell_31_56 m5 : 16|8@1+ (1,-50) [-50|205] "℃"  PC
 SG_ CSC_Tcell_32_56 m5 : 24|8@1+ (1,-50) [-50|205] "℃"  PC
 SG_ CSC_Tcell_33_56 m5 : 32|8@1+ (1,-50) [-50|205] "℃"  PC
 SG_ CSC_Tcell_34_56 m5 : 40|8@1+ (1,-50) [-50|205] "℃"  PC
 SG_ CSC_Tcell_35_56 m5 : 48|8@1+ (1,-50) [-50|205] "℃"  PC
 SG_ CSC_Tcell_36_56 m5 : 56|8@1+ (1,-50) [-50|205] "℃"  PC
 SG_ CSC_Tcell_37_56 m6 : 16|8@1+ (1,-50) [-50|205] "℃"  PC
 SG_ CSC_Tcell_38_56 m6 : 24|8@1+ (1,-50) [-50|205] "℃"  PC
 SG_ CSC_Tcell_39_56 m6 : 32|8@1+ (1,-50) [-50|205] "℃"  PC
 SG_ CSC_Tcell_40_56 m6 : 40|8@1+ (1,-50) [-50|205] "℃"  PC
 SG_ CSC_Tcell_41_56 m6 : 48|8@1+ (1,-50) [-50|205] "℃"  PC
 SG_ CSC_Tcell_42_56 m6 : 56|8@1+ (1,-50) [-50|205] "℃"  PC
 SG_ CSC_Tcell_43_56 m7 : 16|8@1+ (1,-50) [-50|205] "℃"  PC
 SG_ CSC_Tcell_44_56 m7 : 24|8@1+ (1,-50) [-50|205] "℃"  PC
 SG_ CSC_Tcell_45_56 m7 : 32|8@1+ (1,-50) [-50|205] "℃"  PC
 SG_ CSC_Tcell_46_56 m7 : 40|8@1+ (1,-50) [-50|205] "℃"  PC
 SG_ CSC_Tcell_47_56 m7 : 48|8@1+ (1,-50) [-50|205] "℃"  PC
 SG_ CSC_Tcell_48_56 m7 : 56|8@1+ (1,-50) [-50|205] "℃"  PC
 SG_ CSC_Tcell_49_56 m8 : 16|8@1+ (1,-50) [-50|205] "℃"  PC
 SG_ CSC_Tcell_50_56 m8 : 24|8@1+ (1,-50) [-50|205] "℃"  PC
 SG_ CSC_Tcell_51_56 m8 : 32|8@1+ (1,-50) [-50|205] "℃"  PC
 SG_ CSC_Tcell_52_56 m8 : 40|8@1+ (1,-50) [-50|205] "℃"  PC
 SG_ CSC_Tcell_53_56 m8 : 48|8@1+ (1,-50) [-50|205] "℃"  PC
 SG_ CSC_Tcell_54_56 m8 : 56|8@1+ (1,-50) [-50|205] "℃"  PC
 SG_ CSC_Tcell_55_56 m9 : 16|8@1+ (1,-50) [-50|205] "℃"  PC
 SG_ CSC_Tcell_56_56 m9 : 24|8@1+ (1,-50) [-50|205] "℃"  PC
 SG_ CSC_Tcell_57_56 m9 : 32|8@1+ (1,-50) [-50|205] "℃"  PC
 SG_ CSC_Tcell_58_56 m9 : 40|8@1+ (1,-50) [-50|205] "℃"  PC
 SG_ CSC_Tcell_59_56 m9 : 48|8@1+ (1,-50) [-50|205] "℃"  PC
 SG_ CSC_Tcell_60_56 m9 : 56|8@1+ (1,-50) [-50|205] "℃"  PC
 SG_ CSC_Tcell_61_56 m10 : 16|8@1+ (1,-50) [-50|205] "℃"  PC
 SG_ CSC_Tcell_62_56 m10 : 24|8@1+ (1,-50) [-50|205] "℃"  PC
 SG_ CSC_Tcell_63_56 m10 : 32|8@1+ (1,-50) [-50|205] "℃"  PC
 SG_ CSC_Tcell_64_56 m10 : 40|8@1+ (1,-50) [-50|205] "℃"  PC
 SG_ CSC_Tcell_65_56 m10 : 48|8@1+ (1,-50) [-50|205] "℃"  PC
 SG_ CSC_Tcell_66_56 m10 : 56|8@1+ (1,-50) [-50|205] "℃"  PC
 SG_ CSC_Tcell_67_56 m11 : 16|8@1+ (1,-50) [-50|205] "℃"  PC
 SG_ CSC_Tcell_68_56 m11 : 24|8@1+ (1,-50) [-50|205] "℃"  PC
 SG_ CSC_Tcell_69_56 m11 : 32|8@1+ (1,-50) [-50|205] "℃"  PC
 SG_ CSC_Tcell_70_56 m11 : 40|8@1+ (1,-50) [-50|205] "℃"  PC
 SG_ CSC_Tcell_71_56 m11 : 48|8@1+ (1,-50) [-50|205] "℃"  PC
 SG_ CSC_Tcell_72_56 m11 : 56|8@1+ (1,-50) [-50|205] "℃"  PC

BO_ 2400382585 S2P_Detail_Tcell1__57: 8 SBMU
 SG_ CSC_T_No_57 : 0|8@1+ (1,0) [0|255] ""  PC
 SG_ CSC_Tcell_Frame_Index_57 M : 8|8@1+ (1,0) [0|255] ""  PC
 SG_ CSC_Tcell_01_57 m0 : 16|8@1+ (1,-50) [-50|205] "℃"  PC
 SG_ CSC_Tcell_02_57 m0 : 24|8@1+ (1,-50) [-50|205] "℃"  PC
 SG_ CSC_Tcell_03_57 m0 : 32|8@1+ (1,-50) [-50|205] "℃"  PC
 SG_ CSC_Tcell_04_57 m0 : 40|8@1+ (1,-50) [-50|205] "℃"  PC
 SG_ CSC_Tcell_05_57 m0 : 48|8@1+ (1,-50) [-50|205] "℃"  PC
 SG_ CSC_Tcell_06_57 m0 : 56|8@1+ (1,-50) [-50|205] "℃"  PC
 SG_ CSC_Tcell_07_57 m1 : 16|8@1+ (1,-50) [-50|205] "℃"  PC
 SG_ CSC_Tcell_08_57 m1 : 24|8@1+ (1,-50) [-50|205] "℃"  PC
 SG_ CSC_Tcell_09_57 m1 : 32|8@1+ (1,-50) [-50|205] "℃"  PC
 SG_ CSC_Tcell_10_57 m1 : 40|8@1+ (1,-50) [-50|205] "℃"  PC
 SG_ CSC_Tcell_11_57 m1 : 48|8@1+ (1,-50) [-50|205] "℃"  PC
 SG_ CSC_Tcell_12_57 m1 : 56|8@1+ (1,-50) [-50|205] "℃"  PC
 SG_ CSC_Tcell_13_57 m2 : 16|8@1+ (1,-50) [-50|205] "℃"  PC
 SG_ CSC_Tcell_14_57 m2 : 24|8@1+ (1,-50) [-50|205] "℃"  PC
 SG_ CSC_Tcell_15_57 m2 : 32|8@1+ (1,-50) [-50|205] "℃"  PC
 SG_ CSC_Tcell_16_57 m2 : 40|8@1+ (1,-50) [-50|205] "℃"  PC
 SG_ CSC_Tcell_17_57 m2 : 48|8@1+ (1,-50) [-50|205] "℃"  PC
 SG_ CSC_Tcell_18_57 m2 : 56|8@1+ (1,-50) [-50|205] "℃"  PC
 SG_ CSC_Tcell_19_57 m3 : 16|8@1+ (1,-50) [-50|205] "℃"  PC
 SG_ CSC_Tcell_20_57 m3 : 24|8@1+ (1,-50) [-50|205] "℃"  PC
 SG_ CSC_Tcell_21_57 m3 : 32|8@1+ (1,-50) [-50|205] "℃"  PC
 SG_ CSC_Tcell_22_57 m3 : 40|8@1+ (1,-50) [-50|205] "℃"  PC
 SG_ CSC_Tcell_23_57 m3 : 48|8@1+ (1,-50) [-50|205] "℃"  PC
 SG_ CSC_Tcell_24_57 m3 : 56|8@1+ (1,-50) [-50|205] "℃"  PC
 SG_ CSC_Tcell_25_57 m4 : 16|8@1+ (1,-50) [-50|205] "℃"  PC
 SG_ CSC_Tcell_26_57 m4 : 24|8@1+ (1,-50) [-50|205] "℃"  PC
 SG_ CSC_Tcell_27_57 m4 : 32|8@1+ (1,-50) [-50|205] "℃"  PC
 SG_ CSC_Tcell_28_57 m4 : 40|8@1+ (1,-50) [-50|205] "℃"  PC
 SG_ CSC_Tcell_29_57 m4 : 48|8@1+ (1,-50) [-50|205] "℃"  PC
 SG_ CSC_Tcell_30_57 m4 : 56|8@1+ (1,-50) [-50|205] "℃"  PC
 SG_ CSC_Tcell_31_57 m5 : 16|8@1+ (1,-50) [-50|205] "℃"  PC
 SG_ CSC_Tcell_32_57 m5 : 24|8@1+ (1,-50) [-50|205] "℃"  PC
 SG_ CSC_Tcell_33_57 m5 : 32|8@1+ (1,-50) [-50|205] "℃"  PC
 SG_ CSC_Tcell_34_57 m5 : 40|8@1+ (1,-50) [-50|205] "℃"  PC
 SG_ CSC_Tcell_35_57 m5 : 48|8@1+ (1,-50) [-50|205] "℃"  PC
 SG_ CSC_Tcell_36_57 m5 : 56|8@1+ (1,-50) [-50|205] "℃"  PC
 SG_ CSC_Tcell_37_57 m6 : 16|8@1+ (1,-50) [-50|205] "℃"  PC
 SG_ CSC_Tcell_38_57 m6 : 24|8@1+ (1,-50) [-50|205] "℃"  PC
 SG_ CSC_Tcell_39_57 m6 : 32|8@1+ (1,-50) [-50|205] "℃"  PC
 SG_ CSC_Tcell_40_57 m6 : 40|8@1+ (1,-50) [-50|205] "℃"  PC
 SG_ CSC_Tcell_41_57 m6 : 48|8@1+ (1,-50) [-50|205] "℃"  PC
 SG_ CSC_Tcell_42_57 m6 : 56|8@1+ (1,-50) [-50|205] "℃"  PC
 SG_ CSC_Tcell_43_57 m7 : 16|8@1+ (1,-50) [-50|205] "℃"  PC
 SG_ CSC_Tcell_44_57 m7 : 24|8@1+ (1,-50) [-50|205] "℃"  PC
 SG_ CSC_Tcell_45_57 m7 : 32|8@1+ (1,-50) [-50|205] "℃"  PC
 SG_ CSC_Tcell_46_57 m7 : 40|8@1+ (1,-50) [-50|205] "℃"  PC
 SG_ CSC_Tcell_47_57 m7 : 48|8@1+ (1,-50) [-50|205] "℃"  PC
 SG_ CSC_Tcell_48_57 m7 : 56|8@1+ (1,-50) [-50|205] "℃"  PC
 SG_ CSC_Tcell_49_57 m8 : 16|8@1+ (1,-50) [-50|205] "℃"  PC
 SG_ CSC_Tcell_50_57 m8 : 24|8@1+ (1,-50) [-50|205] "℃"  PC
 SG_ CSC_Tcell_51_57 m8 : 32|8@1+ (1,-50) [-50|205] "℃"  PC
 SG_ CSC_Tcell_52_57 m8 : 40|8@1+ (1,-50) [-50|205] "℃"  PC
 SG_ CSC_Tcell_53_57 m8 : 48|8@1+ (1,-50) [-50|205] "℃"  PC
 SG_ CSC_Tcell_54_57 m8 : 56|8@1+ (1,-50) [-50|205] "℃"  PC
 SG_ CSC_Tcell_55_57 m9 : 16|8@1+ (1,-50) [-50|205] "℃"  PC
 SG_ CSC_Tcell_56_57 m9 : 24|8@1+ (1,-50) [-50|205] "℃"  PC
 SG_ CSC_Tcell_57_57 m9 : 32|8@1+ (1,-50) [-50|205] "℃"  PC
 SG_ CSC_Tcell_58_57 m9 : 40|8@1+ (1,-50) [-50|205] "℃"  PC
 SG_ CSC_Tcell_59_57 m9 : 48|8@1+ (1,-50) [-50|205] "℃"  PC
 SG_ CSC_Tcell_60_57 m9 : 56|8@1+ (1,-50) [-50|205] "℃"  PC
 SG_ CSC_Tcell_61_57 m10 : 16|8@1+ (1,-50) [-50|205] "℃"  PC
 SG_ CSC_Tcell_62_57 m10 : 24|8@1+ (1,-50) [-50|205] "℃"  PC
 SG_ CSC_Tcell_63_57 m10 : 32|8@1+ (1,-50) [-50|205] "℃"  PC
 SG_ CSC_Tcell_64_57 m10 : 40|8@1+ (1,-50) [-50|205] "℃"  PC
 SG_ CSC_Tcell_65_57 m10 : 48|8@1+ (1,-50) [-50|205] "℃"  PC
 SG_ CSC_Tcell_66_57 m10 : 56|8@1+ (1,-50) [-50|205] "℃"  PC
 SG_ CSC_Tcell_67_57 m11 : 16|8@1+ (1,-50) [-50|205] "℃"  PC
 SG_ CSC_Tcell_68_57 m11 : 24|8@1+ (1,-50) [-50|205] "℃"  PC
 SG_ CSC_Tcell_69_57 m11 : 32|8@1+ (1,-50) [-50|205] "℃"  PC
 SG_ CSC_Tcell_70_57 m11 : 40|8@1+ (1,-50) [-50|205] "℃"  PC
 SG_ CSC_Tcell_71_57 m11 : 48|8@1+ (1,-50) [-50|205] "℃"  PC
 SG_ CSC_Tcell_72_57 m11 : 56|8@1+ (1,-50) [-50|205] "℃"  PC

BO_ 2400382586 S2P_Detail_Tcell1__58: 8 SBMU
 SG_ CSC_T_No_58 : 0|8@1+ (1,0) [0|255] ""  PC
 SG_ CSC_Tcell_Frame_Index_58 M : 8|8@1+ (1,0) [0|255] ""  PC
 SG_ CSC_Tcell_01_58 m0 : 16|8@1+ (1,-50) [-50|205] "℃"  PC
 SG_ CSC_Tcell_02_58 m0 : 24|8@1+ (1,-50) [-50|205] "℃"  PC
 SG_ CSC_Tcell_03_58 m0 : 32|8@1+ (1,-50) [-50|205] "℃"  PC
 SG_ CSC_Tcell_04_58 m0 : 40|8@1+ (1,-50) [-50|205] "℃"  PC
 SG_ CSC_Tcell_05_58 m0 : 48|8@1+ (1,-50) [-50|205] "℃"  PC
 SG_ CSC_Tcell_06_58 m0 : 56|8@1+ (1,-50) [-50|205] "℃"  PC
 SG_ CSC_Tcell_07_58 m1 : 16|8@1+ (1,-50) [-50|205] "℃"  PC
 SG_ CSC_Tcell_08_58 m1 : 24|8@1+ (1,-50) [-50|205] "℃"  PC
 SG_ CSC_Tcell_09_58 m1 : 32|8@1+ (1,-50) [-50|205] "℃"  PC
 SG_ CSC_Tcell_10_58 m1 : 40|8@1+ (1,-50) [-50|205] "℃"  PC
 SG_ CSC_Tcell_11_58 m1 : 48|8@1+ (1,-50) [-50|205] "℃"  PC
 SG_ CSC_Tcell_12_58 m1 : 56|8@1+ (1,-50) [-50|205] "℃"  PC
 SG_ CSC_Tcell_13_58 m2 : 16|8@1+ (1,-50) [-50|205] "℃"  PC
 SG_ CSC_Tcell_14_58 m2 : 24|8@1+ (1,-50) [-50|205] "℃"  PC
 SG_ CSC_Tcell_15_58 m2 : 32|8@1+ (1,-50) [-50|205] "℃"  PC
 SG_ CSC_Tcell_16_58 m2 : 40|8@1+ (1,-50) [-50|205] "℃"  PC
 SG_ CSC_Tcell_17_58 m2 : 48|8@1+ (1,-50) [-50|205] "℃"  PC
 SG_ CSC_Tcell_18_58 m2 : 56|8@1+ (1,-50) [-50|205] "℃"  PC
 SG_ CSC_Tcell_19_58 m3 : 16|8@1+ (1,-50) [-50|205] "℃"  PC
 SG_ CSC_Tcell_20_58 m3 : 24|8@1+ (1,-50) [-50|205] "℃"  PC
 SG_ CSC_Tcell_21_58 m3 : 32|8@1+ (1,-50) [-50|205] "℃"  PC
 SG_ CSC_Tcell_22_58 m3 : 40|8@1+ (1,-50) [-50|205] "℃"  PC
 SG_ CSC_Tcell_23_58 m3 : 48|8@1+ (1,-50) [-50|205] "℃"  PC
 SG_ CSC_Tcell_24_58 m3 : 56|8@1+ (1,-50) [-50|205] "℃"  PC
 SG_ CSC_Tcell_25_58 m4 : 16|8@1+ (1,-50) [-50|205] "℃"  PC
 SG_ CSC_Tcell_26_58 m4 : 24|8@1+ (1,-50) [-50|205] "℃"  PC
 SG_ CSC_Tcell_27_58 m4 : 32|8@1+ (1,-50) [-50|205] "℃"  PC
 SG_ CSC_Tcell_28_58 m4 : 40|8@1+ (1,-50) [-50|205] "℃"  PC
 SG_ CSC_Tcell_29_58 m4 : 48|8@1+ (1,-50) [-50|205] "℃"  PC
 SG_ CSC_Tcell_30_58 m4 : 56|8@1+ (1,-50) [-50|205] "℃"  PC
 SG_ CSC_Tcell_31_58 m5 : 16|8@1+ (1,-50) [-50|205] "℃"  PC
 SG_ CSC_Tcell_32_58 m5 : 24|8@1+ (1,-50) [-50|205] "℃"  PC
 SG_ CSC_Tcell_33_58 m5 : 32|8@1+ (1,-50) [-50|205] "℃"  PC
 SG_ CSC_Tcell_34_58 m5 : 40|8@1+ (1,-50) [-50|205] "℃"  PC
 SG_ CSC_Tcell_35_58 m5 : 48|8@1+ (1,-50) [-50|205] "℃"  PC
 SG_ CSC_Tcell_36_58 m5 : 56|8@1+ (1,-50) [-50|205] "℃"  PC
 SG_ CSC_Tcell_37_58 m6 : 16|8@1+ (1,-50) [-50|205] "℃"  PC
 SG_ CSC_Tcell_38_58 m6 : 24|8@1+ (1,-50) [-50|205] "℃"  PC
 SG_ CSC_Tcell_39_58 m6 : 32|8@1+ (1,-50) [-50|205] "℃"  PC
 SG_ CSC_Tcell_40_58 m6 : 40|8@1+ (1,-50) [-50|205] "℃"  PC
 SG_ CSC_Tcell_41_58 m6 : 48|8@1+ (1,-50) [-50|205] "℃"  PC
 SG_ CSC_Tcell_42_58 m6 : 56|8@1+ (1,-50) [-50|205] "℃"  PC
 SG_ CSC_Tcell_43_58 m7 : 16|8@1+ (1,-50) [-50|205] "℃"  PC
 SG_ CSC_Tcell_44_58 m7 : 24|8@1+ (1,-50) [-50|205] "℃"  PC
 SG_ CSC_Tcell_45_58 m7 : 32|8@1+ (1,-50) [-50|205] "℃"  PC
 SG_ CSC_Tcell_46_58 m7 : 40|8@1+ (1,-50) [-50|205] "℃"  PC
 SG_ CSC_Tcell_47_58 m7 : 48|8@1+ (1,-50) [-50|205] "℃"  PC
 SG_ CSC_Tcell_48_58 m7 : 56|8@1+ (1,-50) [-50|205] "℃"  PC
 SG_ CSC_Tcell_49_58 m8 : 16|8@1+ (1,-50) [-50|205] "℃"  PC
 SG_ CSC_Tcell_50_58 m8 : 24|8@1+ (1,-50) [-50|205] "℃"  PC
 SG_ CSC_Tcell_51_58 m8 : 32|8@1+ (1,-50) [-50|205] "℃"  PC
 SG_ CSC_Tcell_52_58 m8 : 40|8@1+ (1,-50) [-50|205] "℃"  PC
 SG_ CSC_Tcell_53_58 m8 : 48|8@1+ (1,-50) [-50|205] "℃"  PC
 SG_ CSC_Tcell_54_58 m8 : 56|8@1+ (1,-50) [-50|205] "℃"  PC
 SG_ CSC_Tcell_55_58 m9 : 16|8@1+ (1,-50) [-50|205] "℃"  PC
 SG_ CSC_Tcell_56_58 m9 : 24|8@1+ (1,-50) [-50|205] "℃"  PC
 SG_ CSC_Tcell_57_58 m9 : 32|8@1+ (1,-50) [-50|205] "℃"  PC
 SG_ CSC_Tcell_58_58 m9 : 40|8@1+ (1,-50) [-50|205] "℃"  PC
 SG_ CSC_Tcell_59_58 m9 : 48|8@1+ (1,-50) [-50|205] "℃"  PC
 SG_ CSC_Tcell_60_58 m9 : 56|8@1+ (1,-50) [-50|205] "℃"  PC
 SG_ CSC_Tcell_61_58 m10 : 16|8@1+ (1,-50) [-50|205] "℃"  PC
 SG_ CSC_Tcell_62_58 m10 : 24|8@1+ (1,-50) [-50|205] "℃"  PC
 SG_ CSC_Tcell_63_58 m10 : 32|8@1+ (1,-50) [-50|205] "℃"  PC
 SG_ CSC_Tcell_64_58 m10 : 40|8@1+ (1,-50) [-50|205] "℃"  PC
 SG_ CSC_Tcell_65_58 m10 : 48|8@1+ (1,-50) [-50|205] "℃"  PC
 SG_ CSC_Tcell_66_58 m10 : 56|8@1+ (1,-50) [-50|205] "℃"  PC
 SG_ CSC_Tcell_67_58 m11 : 16|8@1+ (1,-50) [-50|205] "℃"  PC
 SG_ CSC_Tcell_68_58 m11 : 24|8@1+ (1,-50) [-50|205] "℃"  PC
 SG_ CSC_Tcell_69_58 m11 : 32|8@1+ (1,-50) [-50|205] "℃"  PC
 SG_ CSC_Tcell_70_58 m11 : 40|8@1+ (1,-50) [-50|205] "℃"  PC
 SG_ CSC_Tcell_71_58 m11 : 48|8@1+ (1,-50) [-50|205] "℃"  PC
 SG_ CSC_Tcell_72_58 m11 : 56|8@1+ (1,-50) [-50|205] "℃"  PC

BO_ 2400382587 S2P_Detail_Tcell1__59: 8 SBMU
 SG_ CSC_T_No_59 : 0|8@1+ (1,0) [0|255] ""  PC
 SG_ CSC_Tcell_Frame_Index_59 M : 8|8@1+ (1,0) [0|255] ""  PC
 SG_ CSC_Tcell_01_59 m0 : 16|8@1+ (1,-50) [-50|205] "℃"  PC
 SG_ CSC_Tcell_02_59 m0 : 24|8@1+ (1,-50) [-50|205] "℃"  PC
 SG_ CSC_Tcell_03_59 m0 : 32|8@1+ (1,-50) [-50|205] "℃"  PC
 SG_ CSC_Tcell_04_59 m0 : 40|8@1+ (1,-50) [-50|205] "℃"  PC
 SG_ CSC_Tcell_05_59 m0 : 48|8@1+ (1,-50) [-50|205] "℃"  PC
 SG_ CSC_Tcell_06_59 m0 : 56|8@1+ (1,-50) [-50|205] "℃"  PC
 SG_ CSC_Tcell_07_59 m1 : 16|8@1+ (1,-50) [-50|205] "℃"  PC
 SG_ CSC_Tcell_08_59 m1 : 24|8@1+ (1,-50) [-50|205] "℃"  PC
 SG_ CSC_Tcell_09_59 m1 : 32|8@1+ (1,-50) [-50|205] "℃"  PC
 SG_ CSC_Tcell_10_59 m1 : 40|8@1+ (1,-50) [-50|205] "℃"  PC
 SG_ CSC_Tcell_11_59 m1 : 48|8@1+ (1,-50) [-50|205] "℃"  PC
 SG_ CSC_Tcell_12_59 m1 : 56|8@1+ (1,-50) [-50|205] "℃"  PC
 SG_ CSC_Tcell_13_59 m2 : 16|8@1+ (1,-50) [-50|205] "℃"  PC
 SG_ CSC_Tcell_14_59 m2 : 24|8@1+ (1,-50) [-50|205] "℃"  PC
 SG_ CSC_Tcell_15_59 m2 : 32|8@1+ (1,-50) [-50|205] "℃"  PC
 SG_ CSC_Tcell_16_59 m2 : 40|8@1+ (1,-50) [-50|205] "℃"  PC
 SG_ CSC_Tcell_17_59 m2 : 48|8@1+ (1,-50) [-50|205] "℃"  PC
 SG_ CSC_Tcell_18_59 m2 : 56|8@1+ (1,-50) [-50|205] "℃"  PC
 SG_ CSC_Tcell_19_59 m3 : 16|8@1+ (1,-50) [-50|205] "℃"  PC
 SG_ CSC_Tcell_20_59 m3 : 24|8@1+ (1,-50) [-50|205] "℃"  PC
 SG_ CSC_Tcell_21_59 m3 : 32|8@1+ (1,-50) [-50|205] "℃"  PC
 SG_ CSC_Tcell_22_59 m3 : 40|8@1+ (1,-50) [-50|205] "℃"  PC
 SG_ CSC_Tcell_23_59 m3 : 48|8@1+ (1,-50) [-50|205] "℃"  PC
 SG_ CSC_Tcell_24_59 m3 : 56|8@1+ (1,-50) [-50|205] "℃"  PC
 SG_ CSC_Tcell_25_59 m4 : 16|8@1+ (1,-50) [-50|205] "℃"  PC
 SG_ CSC_Tcell_26_59 m4 : 24|8@1+ (1,-50) [-50|205] "℃"  PC
 SG_ CSC_Tcell_27_59 m4 : 32|8@1+ (1,-50) [-50|205] "℃"  PC
 SG_ CSC_Tcell_28_59 m4 : 40|8@1+ (1,-50) [-50|205] "℃"  PC
 SG_ CSC_Tcell_29_59 m4 : 48|8@1+ (1,-50) [-50|205] "℃"  PC
 SG_ CSC_Tcell_30_59 m4 : 56|8@1+ (1,-50) [-50|205] "℃"  PC
 SG_ CSC_Tcell_31_59 m5 : 16|8@1+ (1,-50) [-50|205] "℃"  PC
 SG_ CSC_Tcell_32_59 m5 : 24|8@1+ (1,-50) [-50|205] "℃"  PC
 SG_ CSC_Tcell_33_59 m5 : 32|8@1+ (1,-50) [-50|205] "℃"  PC
 SG_ CSC_Tcell_34_59 m5 : 40|8@1+ (1,-50) [-50|205] "℃"  PC
 SG_ CSC_Tcell_35_59 m5 : 48|8@1+ (1,-50) [-50|205] "℃"  PC
 SG_ CSC_Tcell_36_59 m5 : 56|8@1+ (1,-50) [-50|205] "℃"  PC
 SG_ CSC_Tcell_37_59 m6 : 16|8@1+ (1,-50) [-50|205] "℃"  PC
 SG_ CSC_Tcell_38_59 m6 : 24|8@1+ (1,-50) [-50|205] "℃"  PC
 SG_ CSC_Tcell_39_59 m6 : 32|8@1+ (1,-50) [-50|205] "℃"  PC
 SG_ CSC_Tcell_40_59 m6 : 40|8@1+ (1,-50) [-50|205] "℃"  PC
 SG_ CSC_Tcell_41_59 m6 : 48|8@1+ (1,-50) [-50|205] "℃"  PC
 SG_ CSC_Tcell_42_59 m6 : 56|8@1+ (1,-50) [-50|205] "℃"  PC
 SG_ CSC_Tcell_43_59 m7 : 16|8@1+ (1,-50) [-50|205] "℃"  PC
 SG_ CSC_Tcell_44_59 m7 : 24|8@1+ (1,-50) [-50|205] "℃"  PC
 SG_ CSC_Tcell_45_59 m7 : 32|8@1+ (1,-50) [-50|205] "℃"  PC
 SG_ CSC_Tcell_46_59 m7 : 40|8@1+ (1,-50) [-50|205] "℃"  PC
 SG_ CSC_Tcell_47_59 m7 : 48|8@1+ (1,-50) [-50|205] "℃"  PC
 SG_ CSC_Tcell_48_59 m7 : 56|8@1+ (1,-50) [-50|205] "℃"  PC
 SG_ CSC_Tcell_49_59 m8 : 16|8@1+ (1,-50) [-50|205] "℃"  PC
 SG_ CSC_Tcell_50_59 m8 : 24|8@1+ (1,-50) [-50|205] "℃"  PC
 SG_ CSC_Tcell_51_59 m8 : 32|8@1+ (1,-50) [-50|205] "℃"  PC
 SG_ CSC_Tcell_52_59 m8 : 40|8@1+ (1,-50) [-50|205] "℃"  PC
 SG_ CSC_Tcell_53_59 m8 : 48|8@1+ (1,-50) [-50|205] "℃"  PC
 SG_ CSC_Tcell_54_59 m8 : 56|8@1+ (1,-50) [-50|205] "℃"  PC
 SG_ CSC_Tcell_55_59 m9 : 16|8@1+ (1,-50) [-50|205] "℃"  PC
 SG_ CSC_Tcell_56_59 m9 : 24|8@1+ (1,-50) [-50|205] "℃"  PC
 SG_ CSC_Tcell_57_59 m9 : 32|8@1+ (1,-50) [-50|205] "℃"  PC
 SG_ CSC_Tcell_58_59 m9 : 40|8@1+ (1,-50) [-50|205] "℃"  PC
 SG_ CSC_Tcell_59_59 m9 : 48|8@1+ (1,-50) [-50|205] "℃"  PC
 SG_ CSC_Tcell_60_59 m9 : 56|8@1+ (1,-50) [-50|205] "℃"  PC
 SG_ CSC_Tcell_61_59 m10 : 16|8@1+ (1,-50) [-50|205] "℃"  PC
 SG_ CSC_Tcell_62_59 m10 : 24|8@1+ (1,-50) [-50|205] "℃"  PC
 SG_ CSC_Tcell_63_59 m10 : 32|8@1+ (1,-50) [-50|205] "℃"  PC
 SG_ CSC_Tcell_64_59 m10 : 40|8@1+ (1,-50) [-50|205] "℃"  PC
 SG_ CSC_Tcell_65_59 m10 : 48|8@1+ (1,-50) [-50|205] "℃"  PC
 SG_ CSC_Tcell_66_59 m10 : 56|8@1+ (1,-50) [-50|205] "℃"  PC
 SG_ CSC_Tcell_67_59 m11 : 16|8@1+ (1,-50) [-50|205] "℃"  PC
 SG_ CSC_Tcell_68_59 m11 : 24|8@1+ (1,-50) [-50|205] "℃"  PC
 SG_ CSC_Tcell_69_59 m11 : 32|8@1+ (1,-50) [-50|205] "℃"  PC
 SG_ CSC_Tcell_70_59 m11 : 40|8@1+ (1,-50) [-50|205] "℃"  PC
 SG_ CSC_Tcell_71_59 m11 : 48|8@1+ (1,-50) [-50|205] "℃"  PC
 SG_ CSC_Tcell_72_59 m11 : 56|8@1+ (1,-50) [-50|205] "℃"  PC

BO_ 2400382588 S2P_Detail_Tcell1__60: 8 SBMU
 SG_ CSC_T_No_60 : 0|8@1+ (1,0) [0|255] ""  PC
 SG_ CSC_Tcell_Frame_Index_60 M : 8|8@1+ (1,0) [0|255] ""  PC
 SG_ CSC_Tcell_01_60 m0 : 16|8@1+ (1,-50) [-50|205] "℃"  PC
 SG_ CSC_Tcell_02_60 m0 : 24|8@1+ (1,-50) [-50|205] "℃"  PC
 SG_ CSC_Tcell_03_60 m0 : 32|8@1+ (1,-50) [-50|205] "℃"  PC
 SG_ CSC_Tcell_04_60 m0 : 40|8@1+ (1,-50) [-50|205] "℃"  PC
 SG_ CSC_Tcell_05_60 m0 : 48|8@1+ (1,-50) [-50|205] "℃"  PC
 SG_ CSC_Tcell_06_60 m0 : 56|8@1+ (1,-50) [-50|205] "℃"  PC
 SG_ CSC_Tcell_07_60 m1 : 16|8@1+ (1,-50) [-50|205] "℃"  PC
 SG_ CSC_Tcell_08_60 m1 : 24|8@1+ (1,-50) [-50|205] "℃"  PC
 SG_ CSC_Tcell_09_60 m1 : 32|8@1+ (1,-50) [-50|205] "℃"  PC
 SG_ CSC_Tcell_10_60 m1 : 40|8@1+ (1,-50) [-50|205] "℃"  PC
 SG_ CSC_Tcell_11_60 m1 : 48|8@1+ (1,-50) [-50|205] "℃"  PC
 SG_ CSC_Tcell_12_60 m1 : 56|8@1+ (1,-50) [-50|205] "℃"  PC
 SG_ CSC_Tcell_13_60 m2 : 16|8@1+ (1,-50) [-50|205] "℃"  PC
 SG_ CSC_Tcell_14_60 m2 : 24|8@1+ (1,-50) [-50|205] "℃"  PC
 SG_ CSC_Tcell_15_60 m2 : 32|8@1+ (1,-50) [-50|205] "℃"  PC
 SG_ CSC_Tcell_16_60 m2 : 40|8@1+ (1,-50) [-50|205] "℃"  PC
 SG_ CSC_Tcell_17_60 m2 : 48|8@1+ (1,-50) [-50|205] "℃"  PC
 SG_ CSC_Tcell_18_60 m2 : 56|8@1+ (1,-50) [-50|205] "℃"  PC
 SG_ CSC_Tcell_19_60 m3 : 16|8@1+ (1,-50) [-50|205] "℃"  PC
 SG_ CSC_Tcell_20_60 m3 : 24|8@1+ (1,-50) [-50|205] "℃"  PC
 SG_ CSC_Tcell_21_60 m3 : 32|8@1+ (1,-50) [-50|205] "℃"  PC
 SG_ CSC_Tcell_22_60 m3 : 40|8@1+ (1,-50) [-50|205] "℃"  PC
 SG_ CSC_Tcell_23_60 m3 : 48|8@1+ (1,-50) [-50|205] "℃"  PC
 SG_ CSC_Tcell_24_60 m3 : 56|8@1+ (1,-50) [-50|205] "℃"  PC
 SG_ CSC_Tcell_25_60 m4 : 16|8@1+ (1,-50) [-50|205] "℃"  PC
 SG_ CSC_Tcell_26_60 m4 : 24|8@1+ (1,-50) [-50|205] "℃"  PC
 SG_ CSC_Tcell_27_60 m4 : 32|8@1+ (1,-50) [-50|205] "℃"  PC
 SG_ CSC_Tcell_28_60 m4 : 40|8@1+ (1,-50) [-50|205] "℃"  PC
 SG_ CSC_Tcell_29_60 m4 : 48|8@1+ (1,-50) [-50|205] "℃"  PC
 SG_ CSC_Tcell_30_60 m4 : 56|8@1+ (1,-50) [-50|205] "℃"  PC
 SG_ CSC_Tcell_31_60 m5 : 16|8@1+ (1,-50) [-50|205] "℃"  PC
 SG_ CSC_Tcell_32_60 m5 : 24|8@1+ (1,-50) [-50|205] "℃"  PC
 SG_ CSC_Tcell_33_60 m5 : 32|8@1+ (1,-50) [-50|205] "℃"  PC
 SG_ CSC_Tcell_34_60 m5 : 40|8@1+ (1,-50) [-50|205] "℃"  PC
 SG_ CSC_Tcell_35_60 m5 : 48|8@1+ (1,-50) [-50|205] "℃"  PC
 SG_ CSC_Tcell_36_60 m5 : 56|8@1+ (1,-50) [-50|205] "℃"  PC
 SG_ CSC_Tcell_37_60 m6 : 16|8@1+ (1,-50) [-50|205] "℃"  PC
 SG_ CSC_Tcell_38_60 m6 : 24|8@1+ (1,-50) [-50|205] "℃"  PC
 SG_ CSC_Tcell_39_60 m6 : 32|8@1+ (1,-50) [-50|205] "℃"  PC
 SG_ CSC_Tcell_40_60 m6 : 40|8@1+ (1,-50) [-50|205] "℃"  PC
 SG_ CSC_Tcell_41_60 m6 : 48|8@1+ (1,-50) [-50|205] "℃"  PC
 SG_ CSC_Tcell_42_60 m6 : 56|8@1+ (1,-50) [-50|205] "℃"  PC
 SG_ CSC_Tcell_43_60 m7 : 16|8@1+ (1,-50) [-50|205] "℃"  PC
 SG_ CSC_Tcell_44_60 m7 : 24|8@1+ (1,-50) [-50|205] "℃"  PC
 SG_ CSC_Tcell_45_60 m7 : 32|8@1+ (1,-50) [-50|205] "℃"  PC
 SG_ CSC_Tcell_46_60 m7 : 40|8@1+ (1,-50) [-50|205] "℃"  PC
 SG_ CSC_Tcell_47_60 m7 : 48|8@1+ (1,-50) [-50|205] "℃"  PC
 SG_ CSC_Tcell_48_60 m7 : 56|8@1+ (1,-50) [-50|205] "℃"  PC
 SG_ CSC_Tcell_49_60 m8 : 16|8@1+ (1,-50) [-50|205] "℃"  PC
 SG_ CSC_Tcell_50_60 m8 : 24|8@1+ (1,-50) [-50|205] "℃"  PC
 SG_ CSC_Tcell_51_60 m8 : 32|8@1+ (1,-50) [-50|205] "℃"  PC
 SG_ CSC_Tcell_52_60 m8 : 40|8@1+ (1,-50) [-50|205] "℃"  PC
 SG_ CSC_Tcell_53_60 m8 : 48|8@1+ (1,-50) [-50|205] "℃"  PC
 SG_ CSC_Tcell_54_60 m8 : 56|8@1+ (1,-50) [-50|205] "℃"  PC
 SG_ CSC_Tcell_55_60 m9 : 16|8@1+ (1,-50) [-50|205] "℃"  PC
 SG_ CSC_Tcell_56_60 m9 : 24|8@1+ (1,-50) [-50|205] "℃"  PC
 SG_ CSC_Tcell_57_60 m9 : 32|8@1+ (1,-50) [-50|205] "℃"  PC
 SG_ CSC_Tcell_58_60 m9 : 40|8@1+ (1,-50) [-50|205] "℃"  PC
 SG_ CSC_Tcell_59_60 m9 : 48|8@1+ (1,-50) [-50|205] "℃"  PC
 SG_ CSC_Tcell_60_60 m9 : 56|8@1+ (1,-50) [-50|205] "℃"  PC
 SG_ CSC_Tcell_61_60 m10 : 16|8@1+ (1,-50) [-50|205] "℃"  PC
 SG_ CSC_Tcell_62_60 m10 : 24|8@1+ (1,-50) [-50|205] "℃"  PC
 SG_ CSC_Tcell_63_60 m10 : 32|8@1+ (1,-50) [-50|205] "℃"  PC
 SG_ CSC_Tcell_64_60 m10 : 40|8@1+ (1,-50) [-50|205] "℃"  PC
 SG_ CSC_Tcell_65_60 m10 : 48|8@1+ (1,-50) [-50|205] "℃"  PC
 SG_ CSC_Tcell_66_60 m10 : 56|8@1+ (1,-50) [-50|205] "℃"  PC
 SG_ CSC_Tcell_67_60 m11 : 16|8@1+ (1,-50) [-50|205] "℃"  PC
 SG_ CSC_Tcell_68_60 m11 : 24|8@1+ (1,-50) [-50|205] "℃"  PC
 SG_ CSC_Tcell_69_60 m11 : 32|8@1+ (1,-50) [-50|205] "℃"  PC
 SG_ CSC_Tcell_70_60 m11 : 40|8@1+ (1,-50) [-50|205] "℃"  PC
 SG_ CSC_Tcell_71_60 m11 : 48|8@1+ (1,-50) [-50|205] "℃"  PC
 SG_ CSC_Tcell_72_60 m11 : 56|8@1+ (1,-50) [-50|205] "℃"  PC

BO_ 2400382589 S2P_Detail_Tcell1__61: 8 SBMU
 SG_ CSC_T_No_61 : 0|8@1+ (1,0) [0|255] ""  PC
 SG_ CSC_Tcell_Frame_Index_61 M : 8|8@1+ (1,0) [0|255] ""  PC
 SG_ CSC_Tcell_01_61 m0 : 16|8@1+ (1,-50) [-50|205] "℃"  PC
 SG_ CSC_Tcell_02_61 m0 : 24|8@1+ (1,-50) [-50|205] "℃"  PC
 SG_ CSC_Tcell_03_61 m0 : 32|8@1+ (1,-50) [-50|205] "℃"  PC
 SG_ CSC_Tcell_04_61 m0 : 40|8@1+ (1,-50) [-50|205] "℃"  PC
 SG_ CSC_Tcell_05_61 m0 : 48|8@1+ (1,-50) [-50|205] "℃"  PC
 SG_ CSC_Tcell_06_61 m0 : 56|8@1+ (1,-50) [-50|205] "℃"  PC
 SG_ CSC_Tcell_07_61 m1 : 16|8@1+ (1,-50) [-50|205] "℃"  PC
 SG_ CSC_Tcell_08_61 m1 : 24|8@1+ (1,-50) [-50|205] "℃"  PC
 SG_ CSC_Tcell_09_61 m1 : 32|8@1+ (1,-50) [-50|205] "℃"  PC
 SG_ CSC_Tcell_10_61 m1 : 40|8@1+ (1,-50) [-50|205] "℃"  PC
 SG_ CSC_Tcell_11_61 m1 : 48|8@1+ (1,-50) [-50|205] "℃"  PC
 SG_ CSC_Tcell_12_61 m1 : 56|8@1+ (1,-50) [-50|205] "℃"  PC
 SG_ CSC_Tcell_13_61 m2 : 16|8@1+ (1,-50) [-50|205] "℃"  PC
 SG_ CSC_Tcell_14_61 m2 : 24|8@1+ (1,-50) [-50|205] "℃"  PC
 SG_ CSC_Tcell_15_61 m2 : 32|8@1+ (1,-50) [-50|205] "℃"  PC
 SG_ CSC_Tcell_16_61 m2 : 40|8@1+ (1,-50) [-50|205] "℃"  PC
 SG_ CSC_Tcell_17_61 m2 : 48|8@1+ (1,-50) [-50|205] "℃"  PC
 SG_ CSC_Tcell_18_61 m2 : 56|8@1+ (1,-50) [-50|205] "℃"  PC
 SG_ CSC_Tcell_19_61 m3 : 16|8@1+ (1,-50) [-50|205] "℃"  PC
 SG_ CSC_Tcell_20_61 m3 : 24|8@1+ (1,-50) [-50|205] "℃"  PC
 SG_ CSC_Tcell_21_61 m3 : 32|8@1+ (1,-50) [-50|205] "℃"  PC
 SG_ CSC_Tcell_22_61 m3 : 40|8@1+ (1,-50) [-50|205] "℃"  PC
 SG_ CSC_Tcell_23_61 m3 : 48|8@1+ (1,-50) [-50|205] "℃"  PC
 SG_ CSC_Tcell_24_61 m3 : 56|8@1+ (1,-50) [-50|205] "℃"  PC
 SG_ CSC_Tcell_25_61 m4 : 16|8@1+ (1,-50) [-50|205] "℃"  PC
 SG_ CSC_Tcell_26_61 m4 : 24|8@1+ (1,-50) [-50|205] "℃"  PC
 SG_ CSC_Tcell_27_61 m4 : 32|8@1+ (1,-50) [-50|205] "℃"  PC
 SG_ CSC_Tcell_28_61 m4 : 40|8@1+ (1,-50) [-50|205] "℃"  PC
 SG_ CSC_Tcell_29_61 m4 : 48|8@1+ (1,-50) [-50|205] "℃"  PC
 SG_ CSC_Tcell_30_61 m4 : 56|8@1+ (1,-50) [-50|205] "℃"  PC
 SG_ CSC_Tcell_31_61 m5 : 16|8@1+ (1,-50) [-50|205] "℃"  PC
 SG_ CSC_Tcell_32_61 m5 : 24|8@1+ (1,-50) [-50|205] "℃"  PC
 SG_ CSC_Tcell_33_61 m5 : 32|8@1+ (1,-50) [-50|205] "℃"  PC
 SG_ CSC_Tcell_34_61 m5 : 40|8@1+ (1,-50) [-50|205] "℃"  PC
 SG_ CSC_Tcell_35_61 m5 : 48|8@1+ (1,-50) [-50|205] "℃"  PC
 SG_ CSC_Tcell_36_61 m5 : 56|8@1+ (1,-50) [-50|205] "℃"  PC
 SG_ CSC_Tcell_37_61 m6 : 16|8@1+ (1,-50) [-50|205] "℃"  PC
 SG_ CSC_Tcell_38_61 m6 : 24|8@1+ (1,-50) [-50|205] "℃"  PC
 SG_ CSC_Tcell_39_61 m6 : 32|8@1+ (1,-50) [-50|205] "℃"  PC
 SG_ CSC_Tcell_40_61 m6 : 40|8@1+ (1,-50) [-50|205] "℃"  PC
 SG_ CSC_Tcell_41_61 m6 : 48|8@1+ (1,-50) [-50|205] "℃"  PC
 SG_ CSC_Tcell_42_61 m6 : 56|8@1+ (1,-50) [-50|205] "℃"  PC
 SG_ CSC_Tcell_43_61 m7 : 16|8@1+ (1,-50) [-50|205] "℃"  PC
 SG_ CSC_Tcell_44_61 m7 : 24|8@1+ (1,-50) [-50|205] "℃"  PC
 SG_ CSC_Tcell_45_61 m7 : 32|8@1+ (1,-50) [-50|205] "℃"  PC
 SG_ CSC_Tcell_46_61 m7 : 40|8@1+ (1,-50) [-50|205] "℃"  PC
 SG_ CSC_Tcell_47_61 m7 : 48|8@1+ (1,-50) [-50|205] "℃"  PC
 SG_ CSC_Tcell_48_61 m7 : 56|8@1+ (1,-50) [-50|205] "℃"  PC
 SG_ CSC_Tcell_49_61 m8 : 16|8@1+ (1,-50) [-50|205] "℃"  PC
 SG_ CSC_Tcell_50_61 m8 : 24|8@1+ (1,-50) [-50|205] "℃"  PC
 SG_ CSC_Tcell_51_61 m8 : 32|8@1+ (1,-50) [-50|205] "℃"  PC
 SG_ CSC_Tcell_52_61 m8 : 40|8@1+ (1,-50) [-50|205] "℃"  PC
 SG_ CSC_Tcell_53_61 m8 : 48|8@1+ (1,-50) [-50|205] "℃"  PC
 SG_ CSC_Tcell_54_61 m8 : 56|8@1+ (1,-50) [-50|205] "℃"  PC
 SG_ CSC_Tcell_55_61 m9 : 16|8@1+ (1,-50) [-50|205] "℃"  PC
 SG_ CSC_Tcell_56_61 m9 : 24|8@1+ (1,-50) [-50|205] "℃"  PC
 SG_ CSC_Tcell_57_61 m9 : 32|8@1+ (1,-50) [-50|205] "℃"  PC
 SG_ CSC_Tcell_58_61 m9 : 40|8@1+ (1,-50) [-50|205] "℃"  PC
 SG_ CSC_Tcell_59_61 m9 : 48|8@1+ (1,-50) [-50|205] "℃"  PC
 SG_ CSC_Tcell_60_61 m9 : 56|8@1+ (1,-50) [-50|205] "℃"  PC
 SG_ CSC_Tcell_61_61 m10 : 16|8@1+ (1,-50) [-50|205] "℃"  PC
 SG_ CSC_Tcell_62_61 m10 : 24|8@1+ (1,-50) [-50|205] "℃"  PC
 SG_ CSC_Tcell_63_61 m10 : 32|8@1+ (1,-50) [-50|205] "℃"  PC
 SG_ CSC_Tcell_64_61 m10 : 40|8@1+ (1,-50) [-50|205] "℃"  PC
 SG_ CSC_Tcell_65_61 m10 : 48|8@1+ (1,-50) [-50|205] "℃"  PC
 SG_ CSC_Tcell_66_61 m10 : 56|8@1+ (1,-50) [-50|205] "℃"  PC
 SG_ CSC_Tcell_67_61 m11 : 16|8@1+ (1,-50) [-50|205] "℃"  PC
 SG_ CSC_Tcell_68_61 m11 : 24|8@1+ (1,-50) [-50|205] "℃"  PC
 SG_ CSC_Tcell_69_61 m11 : 32|8@1+ (1,-50) [-50|205] "℃"  PC
 SG_ CSC_Tcell_70_61 m11 : 40|8@1+ (1,-50) [-50|205] "℃"  PC
 SG_ CSC_Tcell_71_61 m11 : 48|8@1+ (1,-50) [-50|205] "℃"  PC
 SG_ CSC_Tcell_72_61 m11 : 56|8@1+ (1,-50) [-50|205] "℃"  PC

BO_ 2400382590 S2P_Detail_Tcell1__62: 8 SBMU
 SG_ CSC_T_No_62 : 0|8@1+ (1,0) [0|255] ""  PC
 SG_ CSC_Tcell_Frame_Index_62 M : 8|8@1+ (1,0) [0|255] ""  PC
 SG_ CSC_Tcell_01_62 m0 : 16|8@1+ (1,-50) [-50|205] "℃"  PC
 SG_ CSC_Tcell_02_62 m0 : 24|8@1+ (1,-50) [-50|205] "℃"  PC
 SG_ CSC_Tcell_03_62 m0 : 32|8@1+ (1,-50) [-50|205] "℃"  PC
 SG_ CSC_Tcell_04_62 m0 : 40|8@1+ (1,-50) [-50|205] "℃"  PC
 SG_ CSC_Tcell_05_62 m0 : 48|8@1+ (1,-50) [-50|205] "℃"  PC
 SG_ CSC_Tcell_06_62 m0 : 56|8@1+ (1,-50) [-50|205] "℃"  PC
 SG_ CSC_Tcell_07_62 m1 : 16|8@1+ (1,-50) [-50|205] "℃"  PC
 SG_ CSC_Tcell_08_62 m1 : 24|8@1+ (1,-50) [-50|205] "℃"  PC
 SG_ CSC_Tcell_09_62 m1 : 32|8@1+ (1,-50) [-50|205] "℃"  PC
 SG_ CSC_Tcell_10_62 m1 : 40|8@1+ (1,-50) [-50|205] "℃"  PC
 SG_ CSC_Tcell_11_62 m1 : 48|8@1+ (1,-50) [-50|205] "℃"  PC
 SG_ CSC_Tcell_12_62 m1 : 56|8@1+ (1,-50) [-50|205] "℃"  PC
 SG_ CSC_Tcell_13_62 m2 : 16|8@1+ (1,-50) [-50|205] "℃"  PC
 SG_ CSC_Tcell_14_62 m2 : 24|8@1+ (1,-50) [-50|205] "℃"  PC
 SG_ CSC_Tcell_15_62 m2 : 32|8@1+ (1,-50) [-50|205] "℃"  PC
 SG_ CSC_Tcell_16_62 m2 : 40|8@1+ (1,-50) [-50|205] "℃"  PC
 SG_ CSC_Tcell_17_62 m2 : 48|8@1+ (1,-50) [-50|205] "℃"  PC
 SG_ CSC_Tcell_18_62 m2 : 56|8@1+ (1,-50) [-50|205] "℃"  PC
 SG_ CSC_Tcell_19_62 m3 : 16|8@1+ (1,-50) [-50|205] "℃"  PC
 SG_ CSC_Tcell_20_62 m3 : 24|8@1+ (1,-50) [-50|205] "℃"  PC
 SG_ CSC_Tcell_21_62 m3 : 32|8@1+ (1,-50) [-50|205] "℃"  PC
 SG_ CSC_Tcell_22_62 m3 : 40|8@1+ (1,-50) [-50|205] "℃"  PC
 SG_ CSC_Tcell_23_62 m3 : 48|8@1+ (1,-50) [-50|205] "℃"  PC
 SG_ CSC_Tcell_24_62 m3 : 56|8@1+ (1,-50) [-50|205] "℃"  PC
 SG_ CSC_Tcell_25_62 m4 : 16|8@1+ (1,-50) [-50|205] "℃"  PC
 SG_ CSC_Tcell_26_62 m4 : 24|8@1+ (1,-50) [-50|205] "℃"  PC
 SG_ CSC_Tcell_27_62 m4 : 32|8@1+ (1,-50) [-50|205] "℃"  PC
 SG_ CSC_Tcell_28_62 m4 : 40|8@1+ (1,-50) [-50|205] "℃"  PC
 SG_ CSC_Tcell_29_62 m4 : 48|8@1+ (1,-50) [-50|205] "℃"  PC
 SG_ CSC_Tcell_30_62 m4 : 56|8@1+ (1,-50) [-50|205] "℃"  PC
 SG_ CSC_Tcell_31_62 m5 : 16|8@1+ (1,-50) [-50|205] "℃"  PC
 SG_ CSC_Tcell_32_62 m5 : 24|8@1+ (1,-50) [-50|205] "℃"  PC
 SG_ CSC_Tcell_33_62 m5 : 32|8@1+ (1,-50) [-50|205] "℃"  PC
 SG_ CSC_Tcell_34_62 m5 : 40|8@1+ (1,-50) [-50|205] "℃"  PC
 SG_ CSC_Tcell_35_62 m5 : 48|8@1+ (1,-50) [-50|205] "℃"  PC
 SG_ CSC_Tcell_36_62 m5 : 56|8@1+ (1,-50) [-50|205] "℃"  PC
 SG_ CSC_Tcell_37_62 m6 : 16|8@1+ (1,-50) [-50|205] "℃"  PC
 SG_ CSC_Tcell_38_62 m6 : 24|8@1+ (1,-50) [-50|205] "℃"  PC
 SG_ CSC_Tcell_39_62 m6 : 32|8@1+ (1,-50) [-50|205] "℃"  PC
 SG_ CSC_Tcell_40_62 m6 : 40|8@1+ (1,-50) [-50|205] "℃"  PC
 SG_ CSC_Tcell_41_62 m6 : 48|8@1+ (1,-50) [-50|205] "℃"  PC
 SG_ CSC_Tcell_42_62 m6 : 56|8@1+ (1,-50) [-50|205] "℃"  PC
 SG_ CSC_Tcell_43_62 m7 : 16|8@1+ (1,-50) [-50|205] "℃"  PC
 SG_ CSC_Tcell_44_62 m7 : 24|8@1+ (1,-50) [-50|205] "℃"  PC
 SG_ CSC_Tcell_45_62 m7 : 32|8@1+ (1,-50) [-50|205] "℃"  PC
 SG_ CSC_Tcell_46_62 m7 : 40|8@1+ (1,-50) [-50|205] "℃"  PC
 SG_ CSC_Tcell_47_62 m7 : 48|8@1+ (1,-50) [-50|205] "℃"  PC
 SG_ CSC_Tcell_48_62 m7 : 56|8@1+ (1,-50) [-50|205] "℃"  PC
 SG_ CSC_Tcell_49_62 m8 : 16|8@1+ (1,-50) [-50|205] "℃"  PC
 SG_ CSC_Tcell_50_62 m8 : 24|8@1+ (1,-50) [-50|205] "℃"  PC
 SG_ CSC_Tcell_51_62 m8 : 32|8@1+ (1,-50) [-50|205] "℃"  PC
 SG_ CSC_Tcell_52_62 m8 : 40|8@1+ (1,-50) [-50|205] "℃"  PC
 SG_ CSC_Tcell_53_62 m8 : 48|8@1+ (1,-50) [-50|205] "℃"  PC
 SG_ CSC_Tcell_54_62 m8 : 56|8@1+ (1,-50) [-50|205] "℃"  PC
 SG_ CSC_Tcell_55_62 m9 : 16|8@1+ (1,-50) [-50|205] "℃"  PC
 SG_ CSC_Tcell_56_62 m9 : 24|8@1+ (1,-50) [-50|205] "℃"  PC
 SG_ CSC_Tcell_57_62 m9 : 32|8@1+ (1,-50) [-50|205] "℃"  PC
 SG_ CSC_Tcell_58_62 m9 : 40|8@1+ (1,-50) [-50|205] "℃"  PC
 SG_ CSC_Tcell_59_62 m9 : 48|8@1+ (1,-50) [-50|205] "℃"  PC
 SG_ CSC_Tcell_60_62 m9 : 56|8@1+ (1,-50) [-50|205] "℃"  PC
 SG_ CSC_Tcell_61_62 m10 : 16|8@1+ (1,-50) [-50|205] "℃"  PC
 SG_ CSC_Tcell_62_62 m10 : 24|8@1+ (1,-50) [-50|205] "℃"  PC
 SG_ CSC_Tcell_63_62 m10 : 32|8@1+ (1,-50) [-50|205] "℃"  PC
 SG_ CSC_Tcell_64_62 m10 : 40|8@1+ (1,-50) [-50|205] "℃"  PC
 SG_ CSC_Tcell_65_62 m10 : 48|8@1+ (1,-50) [-50|205] "℃"  PC
 SG_ CSC_Tcell_66_62 m10 : 56|8@1+ (1,-50) [-50|205] "℃"  PC
 SG_ CSC_Tcell_67_62 m11 : 16|8@1+ (1,-50) [-50|205] "℃"  PC
 SG_ CSC_Tcell_68_62 m11 : 24|8@1+ (1,-50) [-50|205] "℃"  PC
 SG_ CSC_Tcell_69_62 m11 : 32|8@1+ (1,-50) [-50|205] "℃"  PC
 SG_ CSC_Tcell_70_62 m11 : 40|8@1+ (1,-50) [-50|205] "℃"  PC
 SG_ CSC_Tcell_71_62 m11 : 48|8@1+ (1,-50) [-50|205] "℃"  PC
 SG_ CSC_Tcell_72_62 m11 : 56|8@1+ (1,-50) [-50|205] "℃"  PC

BO_ 2400382591 S2P_Detail_Tcell1__63: 8 SBMU
 SG_ CSC_T_No_63 : 0|8@1+ (1,0) [0|255] ""  PC
 SG_ CSC_Tcell_Frame_Index_63 M : 8|8@1+ (1,0) [0|255] ""  PC
 SG_ CSC_Tcell_01_63 m0 : 16|8@1+ (1,-50) [-50|205] "℃"  PC
 SG_ CSC_Tcell_02_63 m0 : 24|8@1+ (1,-50) [-50|205] "℃"  PC
 SG_ CSC_Tcell_03_63 m0 : 32|8@1+ (1,-50) [-50|205] "℃"  PC
 SG_ CSC_Tcell_04_63 m0 : 40|8@1+ (1,-50) [-50|205] "℃"  PC
 SG_ CSC_Tcell_05_63 m0 : 48|8@1+ (1,-50) [-50|205] "℃"  PC
 SG_ CSC_Tcell_06_63 m0 : 56|8@1+ (1,-50) [-50|205] "℃"  PC
 SG_ CSC_Tcell_07_63 m1 : 16|8@1+ (1,-50) [-50|205] "℃"  PC
 SG_ CSC_Tcell_08_63 m1 : 24|8@1+ (1,-50) [-50|205] "℃"  PC
 SG_ CSC_Tcell_09_63 m1 : 32|8@1+ (1,-50) [-50|205] "℃"  PC
 SG_ CSC_Tcell_10_63 m1 : 40|8@1+ (1,-50) [-50|205] "℃"  PC
 SG_ CSC_Tcell_11_63 m1 : 48|8@1+ (1,-50) [-50|205] "℃"  PC
 SG_ CSC_Tcell_12_63 m1 : 56|8@1+ (1,-50) [-50|205] "℃"  PC
 SG_ CSC_Tcell_13_63 m2 : 16|8@1+ (1,-50) [-50|205] "℃"  PC
 SG_ CSC_Tcell_14_63 m2 : 24|8@1+ (1,-50) [-50|205] "℃"  PC
 SG_ CSC_Tcell_15_63 m2 : 32|8@1+ (1,-50) [-50|205] "℃"  PC
 SG_ CSC_Tcell_16_63 m2 : 40|8@1+ (1,-50) [-50|205] "℃"  PC
 SG_ CSC_Tcell_17_63 m2 : 48|8@1+ (1,-50) [-50|205] "℃"  PC
 SG_ CSC_Tcell_18_63 m2 : 56|8@1+ (1,-50) [-50|205] "℃"  PC
 SG_ CSC_Tcell_19_63 m3 : 16|8@1+ (1,-50) [-50|205] "℃"  PC
 SG_ CSC_Tcell_20_63 m3 : 24|8@1+ (1,-50) [-50|205] "℃"  PC
 SG_ CSC_Tcell_21_63 m3 : 32|8@1+ (1,-50) [-50|205] "℃"  PC
 SG_ CSC_Tcell_22_63 m3 : 40|8@1+ (1,-50) [-50|205] "℃"  PC
 SG_ CSC_Tcell_23_63 m3 : 48|8@1+ (1,-50) [-50|205] "℃"  PC
 SG_ CSC_Tcell_24_63 m3 : 56|8@1+ (1,-50) [-50|205] "℃"  PC
 SG_ CSC_Tcell_25_63 m4 : 16|8@1+ (1,-50) [-50|205] "℃"  PC
 SG_ CSC_Tcell_26_63 m4 : 24|8@1+ (1,-50) [-50|205] "℃"  PC
 SG_ CSC_Tcell_27_63 m4 : 32|8@1+ (1,-50) [-50|205] "℃"  PC
 SG_ CSC_Tcell_28_63 m4 : 40|8@1+ (1,-50) [-50|205] "℃"  PC
 SG_ CSC_Tcell_29_63 m4 : 48|8@1+ (1,-50) [-50|205] "℃"  PC
 SG_ CSC_Tcell_30_63 m4 : 56|8@1+ (1,-50) [-50|205] "℃"  PC
 SG_ CSC_Tcell_31_63 m5 : 16|8@1+ (1,-50) [-50|205] "℃"  PC
 SG_ CSC_Tcell_32_63 m5 : 24|8@1+ (1,-50) [-50|205] "℃"  PC
 SG_ CSC_Tcell_33_63 m5 : 32|8@1+ (1,-50) [-50|205] "℃"  PC
 SG_ CSC_Tcell_34_63 m5 : 40|8@1+ (1,-50) [-50|205] "℃"  PC
 SG_ CSC_Tcell_35_63 m5 : 48|8@1+ (1,-50) [-50|205] "℃"  PC
 SG_ CSC_Tcell_36_63 m5 : 56|8@1+ (1,-50) [-50|205] "℃"  PC
 SG_ CSC_Tcell_37_63 m6 : 16|8@1+ (1,-50) [-50|205] "℃"  PC
 SG_ CSC_Tcell_38_63 m6 : 24|8@1+ (1,-50) [-50|205] "℃"  PC
 SG_ CSC_Tcell_39_63 m6 : 32|8@1+ (1,-50) [-50|205] "℃"  PC
 SG_ CSC_Tcell_40_63 m6 : 40|8@1+ (1,-50) [-50|205] "℃"  PC
 SG_ CSC_Tcell_41_63 m6 : 48|8@1+ (1,-50) [-50|205] "℃"  PC
 SG_ CSC_Tcell_42_63 m6 : 56|8@1+ (1,-50) [-50|205] "℃"  PC
 SG_ CSC_Tcell_43_63 m7 : 16|8@1+ (1,-50) [-50|205] "℃"  PC
 SG_ CSC_Tcell_44_63 m7 : 24|8@1+ (1,-50) [-50|205] "℃"  PC
 SG_ CSC_Tcell_45_63 m7 : 32|8@1+ (1,-50) [-50|205] "℃"  PC
 SG_ CSC_Tcell_46_63 m7 : 40|8@1+ (1,-50) [-50|205] "℃"  PC
 SG_ CSC_Tcell_47_63 m7 : 48|8@1+ (1,-50) [-50|205] "℃"  PC
 SG_ CSC_Tcell_48_63 m7 : 56|8@1+ (1,-50) [-50|205] "℃"  PC
 SG_ CSC_Tcell_49_63 m8 : 16|8@1+ (1,-50) [-50|205] "℃"  PC
 SG_ CSC_Tcell_50_63 m8 : 24|8@1+ (1,-50) [-50|205] "℃"  PC
 SG_ CSC_Tcell_51_63 m8 : 32|8@1+ (1,-50) [-50|205] "℃"  PC
 SG_ CSC_Tcell_52_63 m8 : 40|8@1+ (1,-50) [-50|205] "℃"  PC
 SG_ CSC_Tcell_53_63 m8 : 48|8@1+ (1,-50) [-50|205] "℃"  PC
 SG_ CSC_Tcell_54_63 m8 : 56|8@1+ (1,-50) [-50|205] "℃"  PC
 SG_ CSC_Tcell_55_63 m9 : 16|8@1+ (1,-50) [-50|205] "℃"  PC
 SG_ CSC_Tcell_56_63 m9 : 24|8@1+ (1,-50) [-50|205] "℃"  PC
 SG_ CSC_Tcell_57_63 m9 : 32|8@1+ (1,-50) [-50|205] "℃"  PC
 SG_ CSC_Tcell_58_63 m9 : 40|8@1+ (1,-50) [-50|205] "℃"  PC
 SG_ CSC_Tcell_59_63 m9 : 48|8@1+ (1,-50) [-50|205] "℃"  PC
 SG_ CSC_Tcell_60_63 m9 : 56|8@1+ (1,-50) [-50|205] "℃"  PC
 SG_ CSC_Tcell_61_63 m10 : 16|8@1+ (1,-50) [-50|205] "℃"  PC
 SG_ CSC_Tcell_62_63 m10 : 24|8@1+ (1,-50) [-50|205] "℃"  PC
 SG_ CSC_Tcell_63_63 m10 : 32|8@1+ (1,-50) [-50|205] "℃"  PC
 SG_ CSC_Tcell_64_63 m10 : 40|8@1+ (1,-50) [-50|205] "℃"  PC
 SG_ CSC_Tcell_65_63 m10 : 48|8@1+ (1,-50) [-50|205] "℃"  PC
 SG_ CSC_Tcell_66_63 m10 : 56|8@1+ (1,-50) [-50|205] "℃"  PC
 SG_ CSC_Tcell_67_63 m11 : 16|8@1+ (1,-50) [-50|205] "℃"  PC
 SG_ CSC_Tcell_68_63 m11 : 24|8@1+ (1,-50) [-50|205] "℃"  PC
 SG_ CSC_Tcell_69_63 m11 : 32|8@1+ (1,-50) [-50|205] "℃"  PC
 SG_ CSC_Tcell_70_63 m11 : 40|8@1+ (1,-50) [-50|205] "℃"  PC
 SG_ CSC_Tcell_71_63 m11 : 48|8@1+ (1,-50) [-50|205] "℃"  PC
 SG_ CSC_Tcell_72_63 m11 : 56|8@1+ (1,-50) [-50|205] "℃"  PC

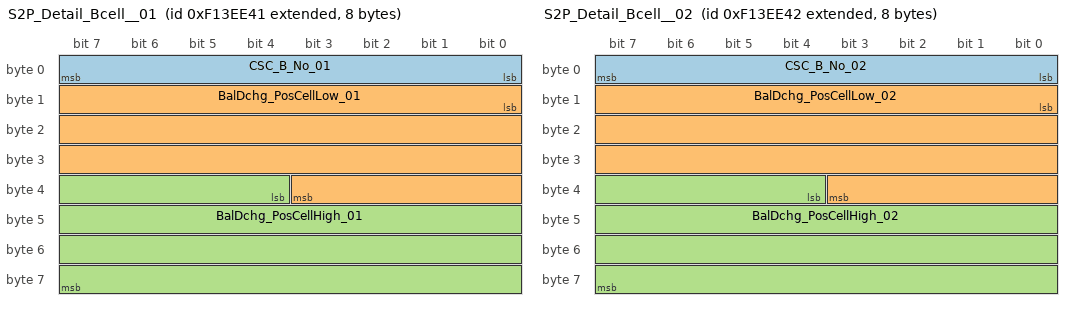
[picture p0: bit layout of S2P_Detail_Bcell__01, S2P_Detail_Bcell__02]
BO_ 2400448065 S2P_Detail_Bcell__01: 8 SBMU
 SG_ CSC_B_No_01 : 0|8@1+ (1,0) [0|255] ""  PC
 SG_ BalDchg_PosCellLow_01 : 8|28@1+ (1,0) [0|268435455] ""  PC
 SG_ BalDchg_PosCellHigh_01 : 36|28@1+ (1,0) [0|268435455] ""  PC

BO_ 2400448066 S2P_Detail_Bcell__02: 8 SBMU
 SG_ CSC_B_No_02 : 0|8@1+ (1,0) [0|255] ""  PC
 SG_ BalDchg_PosCellLow_02 : 8|28@1+ (1,0) [0|268435455] ""  PC
 SG_ BalDchg_PosCellHigh_02 : 36|28@1+ (1,0) [0|268435455] ""  PC

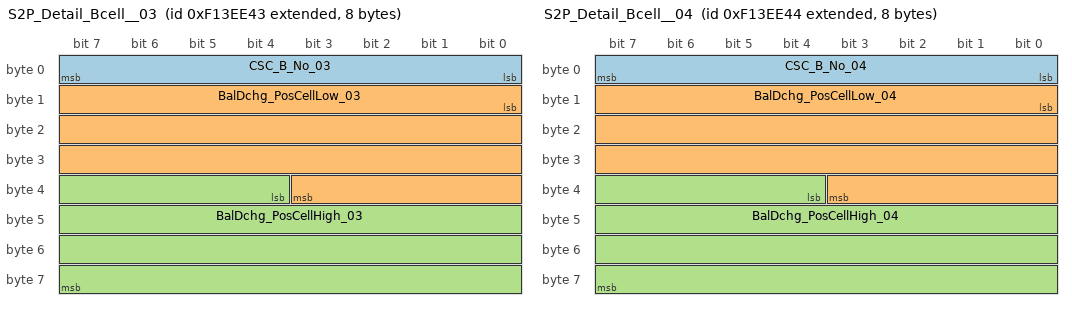
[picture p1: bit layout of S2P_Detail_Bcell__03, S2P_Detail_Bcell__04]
BO_ 2400448067 S2P_Detail_Bcell__03: 8 SBMU
 SG_ CSC_B_No_03 : 0|8@1+ (1,0) [0|255] ""  PC
 SG_ BalDchg_PosCellLow_03 : 8|28@1+ (1,0) [0|268435455] ""  PC
 SG_ BalDchg_PosCellHigh_03 : 36|28@1+ (1,0) [0|268435455] ""  PC

BO_ 2400448068 S2P_Detail_Bcell__04: 8 SBMU
 SG_ CSC_B_No_04 : 0|8@1+ (1,0) [0|255] ""  PC
 SG_ BalDchg_PosCellLow_04 : 8|28@1+ (1,0) [0|268435455] ""  PC
 SG_ BalDchg_PosCellHigh_04 : 36|28@1+ (1,0) [0|268435455] ""  PC

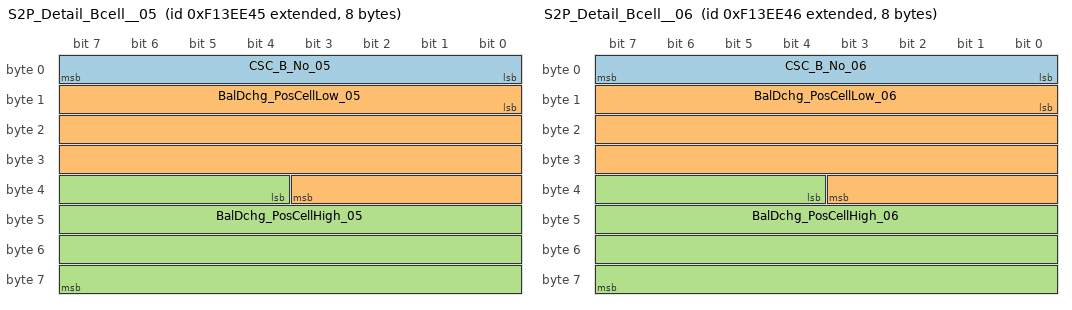
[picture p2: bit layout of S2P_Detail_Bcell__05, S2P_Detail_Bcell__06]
BO_ 2400448069 S2P_Detail_Bcell__05: 8 SBMU
 SG_ CSC_B_No_05 : 0|8@1+ (1,0) [0|255] ""  PC
 SG_ BalDchg_PosCellLow_05 : 8|28@1+ (1,0) [0|268435455] ""  PC
 SG_ BalDchg_PosCellHigh_05 : 36|28@1+ (1,0) [0|268435455] ""  PC

BO_ 2400448070 S2P_Detail_Bcell__06: 8 SBMU
 SG_ CSC_B_No_06 : 0|8@1+ (1,0) [0|255] ""  PC
 SG_ BalDchg_PosCellLow_06 : 8|28@1+ (1,0) [0|268435455] ""  PC
 SG_ BalDchg_PosCellHigh_06 : 36|28@1+ (1,0) [0|268435455] ""  PC

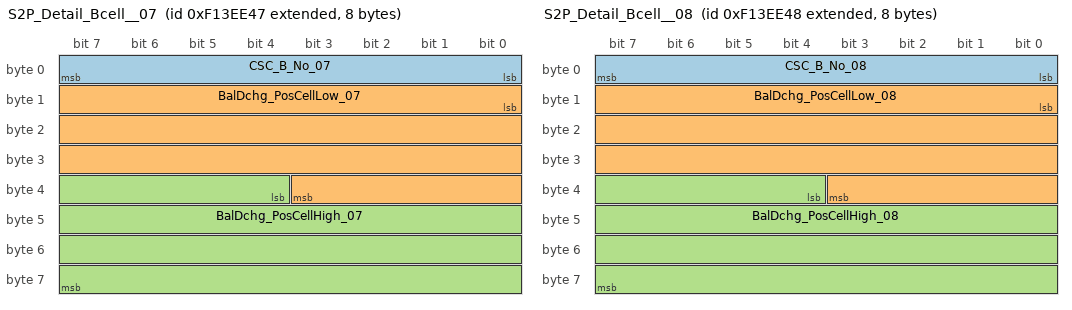
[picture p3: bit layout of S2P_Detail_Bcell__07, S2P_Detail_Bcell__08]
BO_ 2400448071 S2P_Detail_Bcell__07: 8 SBMU
 SG_ CSC_B_No_07 : 0|8@1+ (1,0) [0|255] ""  PC
 SG_ BalDchg_PosCellLow_07 : 8|28@1+ (1,0) [0|268435455] ""  PC
 SG_ BalDchg_PosCellHigh_07 : 36|28@1+ (1,0) [0|268435455] ""  PC

BO_ 2400448072 S2P_Detail_Bcell__08: 8 SBMU
 SG_ CSC_B_No_08 : 0|8@1+ (1,0) [0|255] ""  PC
 SG_ BalDchg_PosCellLow_08 : 8|28@1+ (1,0) [0|268435455] ""  PC
 SG_ BalDchg_PosCellHigh_08 : 36|28@1+ (1,0) [0|268435455] ""  PC

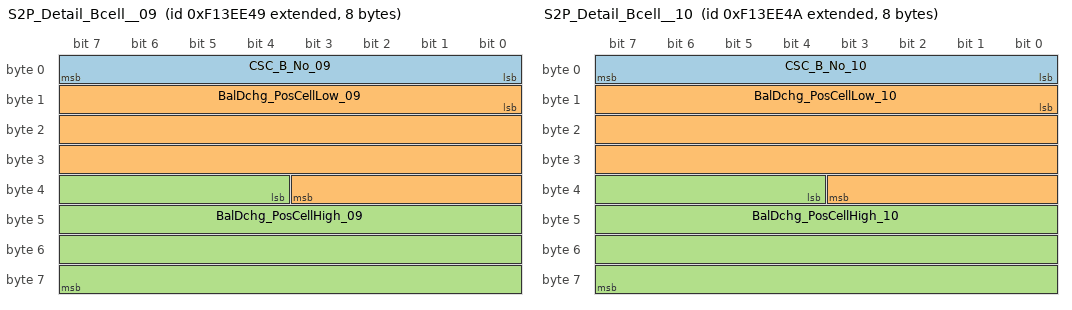
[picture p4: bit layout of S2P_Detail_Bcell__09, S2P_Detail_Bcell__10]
BO_ 2400448073 S2P_Detail_Bcell__09: 8 SBMU
 SG_ CSC_B_No_09 : 0|8@1+ (1,0) [0|255] ""  PC
 SG_ BalDchg_PosCellLow_09 : 8|28@1+ (1,0) [0|268435455] ""  PC
 SG_ BalDchg_PosCellHigh_09 : 36|28@1+ (1,0) [0|268435455] ""  PC

BO_ 2400448074 S2P_Detail_Bcell__10: 8 SBMU
 SG_ CSC_B_No_10 : 0|8@1+ (1,0) [0|255] ""  PC
 SG_ BalDchg_PosCellLow_10 : 8|28@1+ (1,0) [0|268435455] ""  PC
 SG_ BalDchg_PosCellHigh_10 : 36|28@1+ (1,0) [0|268435455] ""  PC

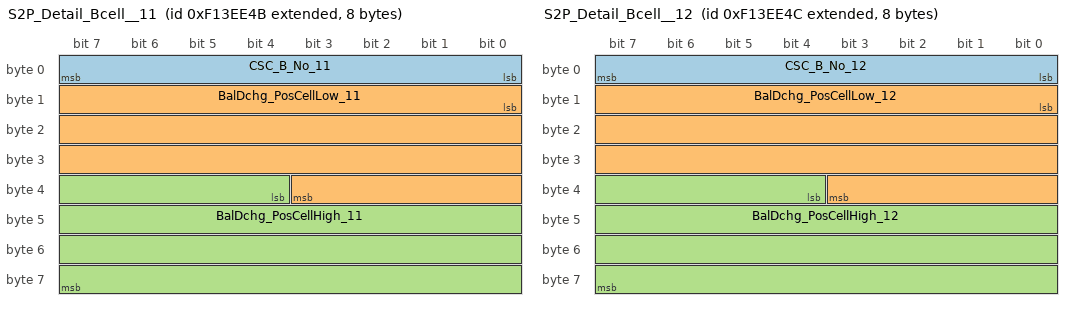
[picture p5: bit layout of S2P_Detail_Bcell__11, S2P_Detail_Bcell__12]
BO_ 2400448075 S2P_Detail_Bcell__11: 8 SBMU
 SG_ CSC_B_No_11 : 0|8@1+ (1,0) [0|255] ""  PC
 SG_ BalDchg_PosCellLow_11 : 8|28@1+ (1,0) [0|268435455] ""  PC
 SG_ BalDchg_PosCellHigh_11 : 36|28@1+ (1,0) [0|268435455] ""  PC

BO_ 2400448076 S2P_Detail_Bcell__12: 8 SBMU
 SG_ CSC_B_No_12 : 0|8@1+ (1,0) [0|255] ""  PC
 SG_ BalDchg_PosCellLow_12 : 8|28@1+ (1,0) [0|268435455] ""  PC
 SG_ BalDchg_PosCellHigh_12 : 36|28@1+ (1,0) [0|268435455] ""  PC

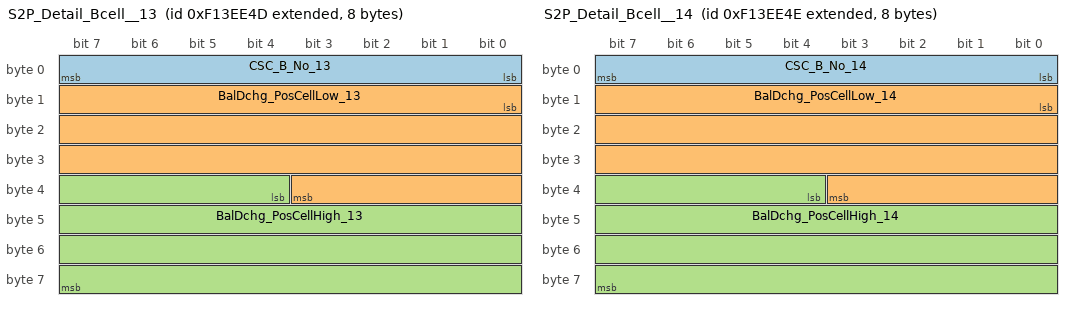
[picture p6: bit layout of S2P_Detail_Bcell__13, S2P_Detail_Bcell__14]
BO_ 2400448077 S2P_Detail_Bcell__13: 8 SBMU
 SG_ CSC_B_No_13 : 0|8@1+ (1,0) [0|255] ""  PC
 SG_ BalDchg_PosCellLow_13 : 8|28@1+ (1,0) [0|268435455] ""  PC
 SG_ BalDchg_PosCellHigh_13 : 36|28@1+ (1,0) [0|268435455] ""  PC

BO_ 2400448078 S2P_Detail_Bcell__14: 8 SBMU
 SG_ CSC_B_No_14 : 0|8@1+ (1,0) [0|255] ""  PC
 SG_ BalDchg_PosCellLow_14 : 8|28@1+ (1,0) [0|268435455] ""  PC
 SG_ BalDchg_PosCellHigh_14 : 36|28@1+ (1,0) [0|268435455] ""  PC

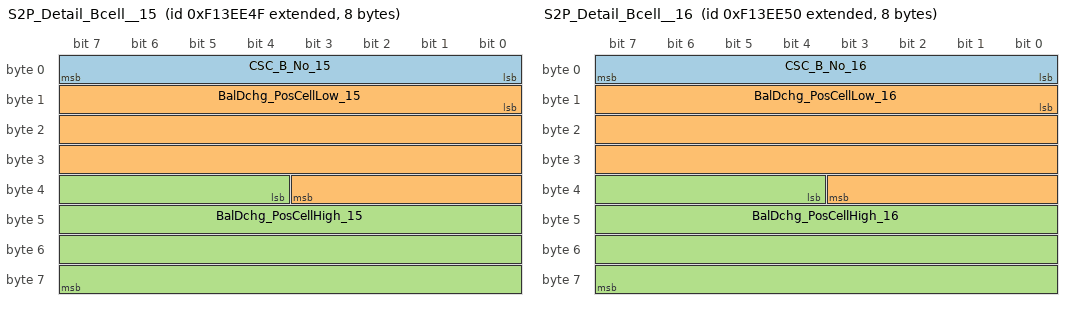
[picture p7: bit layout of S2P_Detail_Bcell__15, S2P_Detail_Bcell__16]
BO_ 2400448079 S2P_Detail_Bcell__15: 8 SBMU
 SG_ CSC_B_No_15 : 0|8@1+ (1,0) [0|255] ""  PC
 SG_ BalDchg_PosCellLow_15 : 8|28@1+ (1,0) [0|268435455] ""  PC
 SG_ BalDchg_PosCellHigh_15 : 36|28@1+ (1,0) [0|268435455] ""  PC

BO_ 2400448080 S2P_Detail_Bcell__16: 8 SBMU
 SG_ CSC_B_No_16 : 0|8@1+ (1,0) [0|255] ""  PC
 SG_ BalDchg_PosCellLow_16 : 8|28@1+ (1,0) [0|268435455] ""  PC
 SG_ BalDchg_PosCellHigh_16 : 36|28@1+ (1,0) [0|268435455] ""  PC

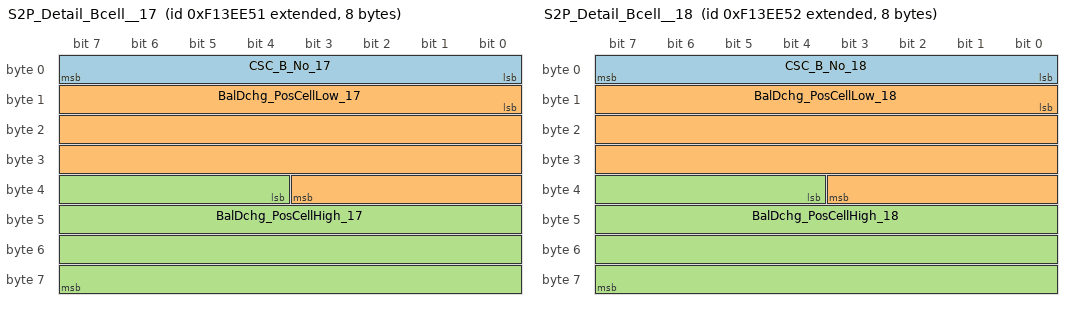
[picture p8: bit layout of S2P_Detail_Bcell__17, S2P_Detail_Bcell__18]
BO_ 2400448081 S2P_Detail_Bcell__17: 8 SBMU
 SG_ CSC_B_No_17 : 0|8@1+ (1,0) [0|255] ""  PC
 SG_ BalDchg_PosCellLow_17 : 8|28@1+ (1,0) [0|268435455] ""  PC
 SG_ BalDchg_PosCellHigh_17 : 36|28@1+ (1,0) [0|268435455] ""  PC

BO_ 2400448082 S2P_Detail_Bcell__18: 8 SBMU
 SG_ CSC_B_No_18 : 0|8@1+ (1,0) [0|255] ""  PC
 SG_ BalDchg_PosCellLow_18 : 8|28@1+ (1,0) [0|268435455] ""  PC
 SG_ BalDchg_PosCellHigh_18 : 36|28@1+ (1,0) [0|268435455] ""  PC

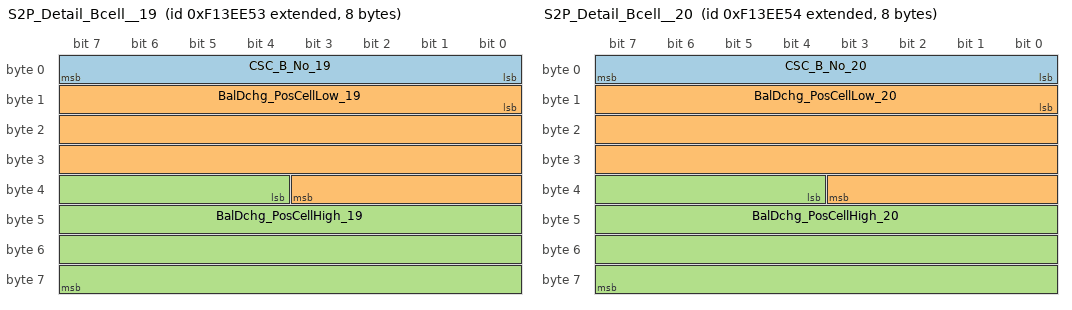
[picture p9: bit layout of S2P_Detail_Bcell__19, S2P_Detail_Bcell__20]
BO_ 2400448083 S2P_Detail_Bcell__19: 8 SBMU
 SG_ CSC_B_No_19 : 0|8@1+ (1,0) [0|255] ""  PC
 SG_ BalDchg_PosCellLow_19 : 8|28@1+ (1,0) [0|268435455] ""  PC
 SG_ BalDchg_PosCellHigh_19 : 36|28@1+ (1,0) [0|268435455] ""  PC

BO_ 2400448084 S2P_Detail_Bcell__20: 8 SBMU
 SG_ CSC_B_No_20 : 0|8@1+ (1,0) [0|255] ""  PC
 SG_ BalDchg_PosCellLow_20 : 8|28@1+ (1,0) [0|268435455] ""  PC
 SG_ BalDchg_PosCellHigh_20 : 36|28@1+ (1,0) [0|268435455] ""  PC

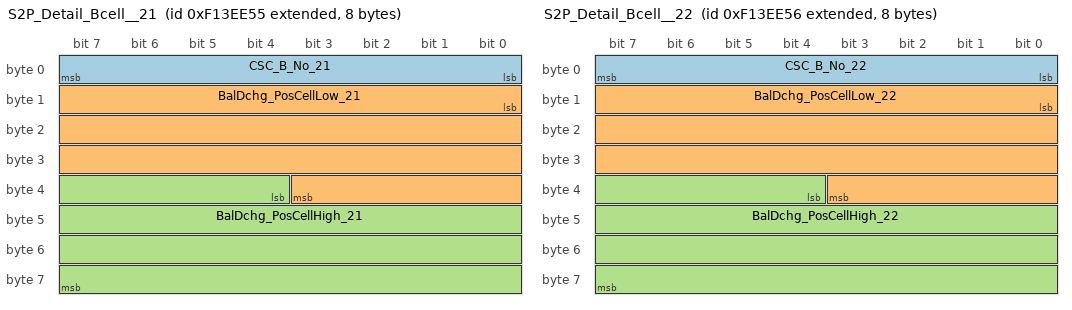
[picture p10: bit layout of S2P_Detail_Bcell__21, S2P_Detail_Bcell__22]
BO_ 2400448085 S2P_Detail_Bcell__21: 8 SBMU
 SG_ CSC_B_No_21 : 0|8@1+ (1,0) [0|255] ""  PC
 SG_ BalDchg_PosCellLow_21 : 8|28@1+ (1,0) [0|268435455] ""  PC
 SG_ BalDchg_PosCellHigh_21 : 36|28@1+ (1,0) [0|268435455] ""  PC

BO_ 2400448086 S2P_Detail_Bcell__22: 8 SBMU
 SG_ CSC_B_No_22 : 0|8@1+ (1,0) [0|255] ""  PC
 SG_ BalDchg_PosCellLow_22 : 8|28@1+ (1,0) [0|268435455] ""  PC
 SG_ BalDchg_PosCellHigh_22 : 36|28@1+ (1,0) [0|268435455] ""  PC

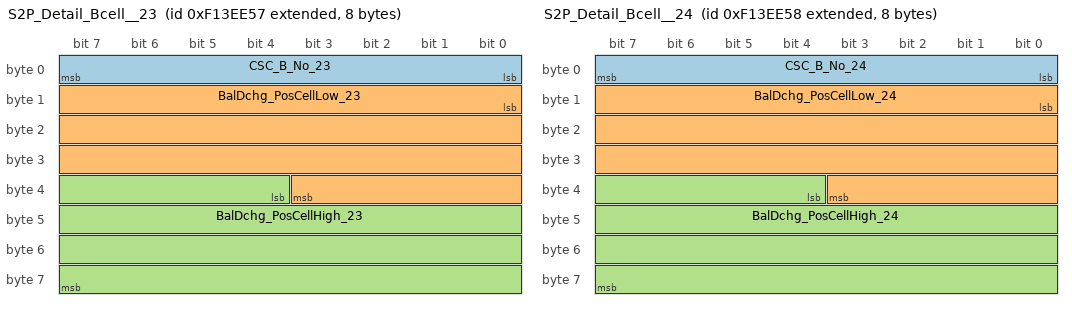
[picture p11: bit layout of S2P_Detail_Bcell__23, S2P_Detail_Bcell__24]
BO_ 2400448087 S2P_Detail_Bcell__23: 8 SBMU
 SG_ CSC_B_No_23 : 0|8@1+ (1,0) [0|255] ""  PC
 SG_ BalDchg_PosCellLow_23 : 8|28@1+ (1,0) [0|268435455] ""  PC
 SG_ BalDchg_PosCellHigh_23 : 36|28@1+ (1,0) [0|268435455] ""  PC

BO_ 2400448088 S2P_Detail_Bcell__24: 8 SBMU
 SG_ CSC_B_No_24 : 0|8@1+ (1,0) [0|255] ""  PC
 SG_ BalDchg_PosCellLow_24 : 8|28@1+ (1,0) [0|268435455] ""  PC
 SG_ BalDchg_PosCellHigh_24 : 36|28@1+ (1,0) [0|268435455] ""  PC

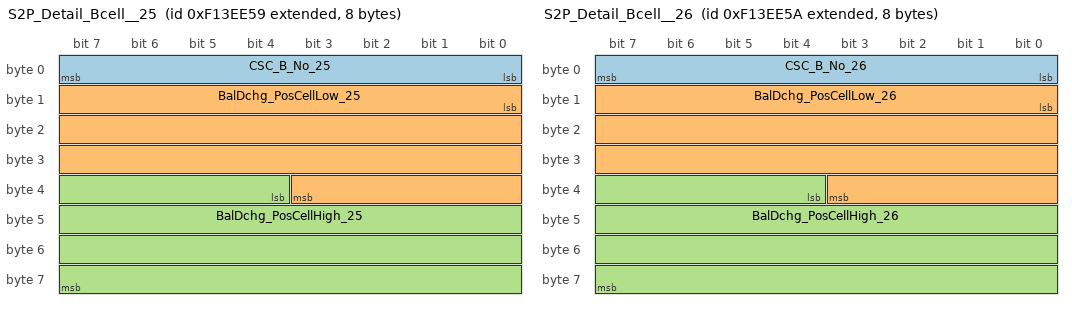
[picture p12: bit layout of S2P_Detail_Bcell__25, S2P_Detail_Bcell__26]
BO_ 2400448089 S2P_Detail_Bcell__25: 8 SBMU
 SG_ CSC_B_No_25 : 0|8@1+ (1,0) [0|255] ""  PC
 SG_ BalDchg_PosCellLow_25 : 8|28@1+ (1,0) [0|268435455] ""  PC
 SG_ BalDchg_PosCellHigh_25 : 36|28@1+ (1,0) [0|268435455] ""  PC

BO_ 2400448090 S2P_Detail_Bcell__26: 8 SBMU
 SG_ CSC_B_No_26 : 0|8@1+ (1,0) [0|255] ""  PC
 SG_ BalDchg_PosCellLow_26 : 8|28@1+ (1,0) [0|268435455] ""  PC
 SG_ BalDchg_PosCellHigh_26 : 36|28@1+ (1,0) [0|268435455] ""  PC

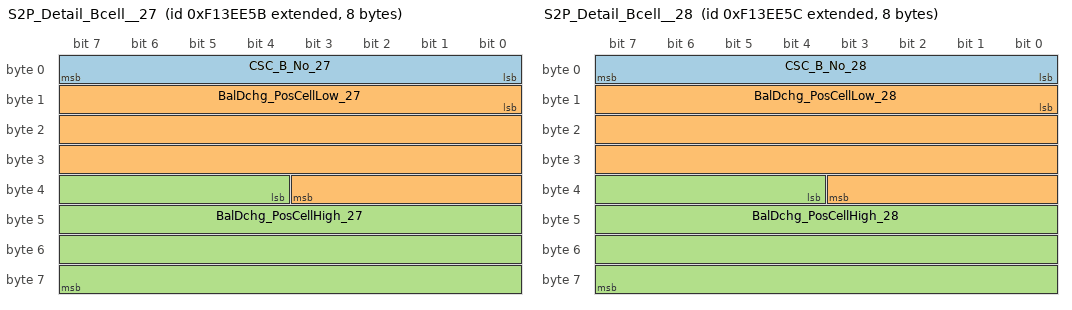
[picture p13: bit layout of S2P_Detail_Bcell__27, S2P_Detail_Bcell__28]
BO_ 2400448091 S2P_Detail_Bcell__27: 8 SBMU
 SG_ CSC_B_No_27 : 0|8@1+ (1,0) [0|255] ""  PC
 SG_ BalDchg_PosCellLow_27 : 8|28@1+ (1,0) [0|268435455] ""  PC
 SG_ BalDchg_PosCellHigh_27 : 36|28@1+ (1,0) [0|268435455] ""  PC

BO_ 2400448092 S2P_Detail_Bcell__28: 8 SBMU
 SG_ CSC_B_No_28 : 0|8@1+ (1,0) [0|255] ""  PC
 SG_ BalDchg_PosCellLow_28 : 8|28@1+ (1,0) [0|268435455] ""  PC
 SG_ BalDchg_PosCellHigh_28 : 36|28@1+ (1,0) [0|268435455] ""  PC

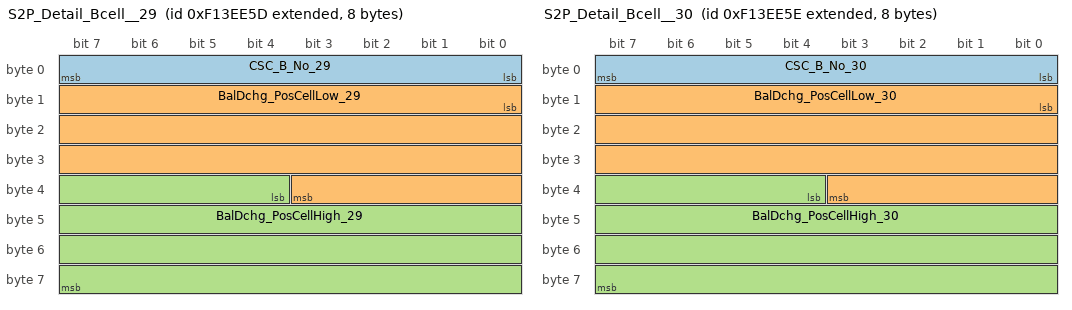
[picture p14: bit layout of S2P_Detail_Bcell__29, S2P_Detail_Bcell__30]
BO_ 2400448093 S2P_Detail_Bcell__29: 8 SBMU
 SG_ CSC_B_No_29 : 0|8@1+ (1,0) [0|255] ""  PC
 SG_ BalDchg_PosCellLow_29 : 8|28@1+ (1,0) [0|268435455] ""  PC
 SG_ BalDchg_PosCellHigh_29 : 36|28@1+ (1,0) [0|268435455] ""  PC

BO_ 2400448094 S2P_Detail_Bcell__30: 8 SBMU
 SG_ CSC_B_No_30 : 0|8@1+ (1,0) [0|255] ""  PC
 SG_ BalDchg_PosCellLow_30 : 8|28@1+ (1,0) [0|268435455] ""  PC
 SG_ BalDchg_PosCellHigh_30 : 36|28@1+ (1,0) [0|268435455] ""  PC

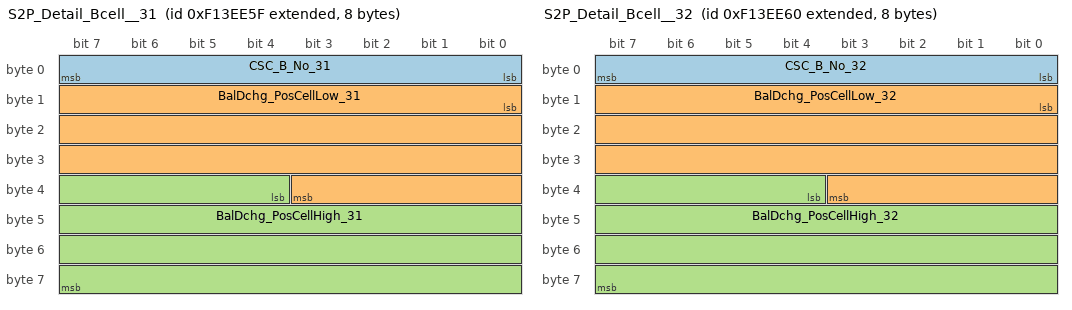
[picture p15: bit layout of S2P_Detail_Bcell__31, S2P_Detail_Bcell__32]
BO_ 2400448095 S2P_Detail_Bcell__31: 8 SBMU
 SG_ CSC_B_No_31 : 0|8@1+ (1,0) [0|255] ""  PC
 SG_ BalDchg_PosCellLow_31 : 8|28@1+ (1,0) [0|268435455] ""  PC
 SG_ BalDchg_PosCellHigh_31 : 36|28@1+ (1,0) [0|268435455] ""  PC

BO_ 2400448096 S2P_Detail_Bcell__32: 8 SBMU
 SG_ CSC_B_No_32 : 0|8@1+ (1,0) [0|255] ""  PC
 SG_ BalDchg_PosCellLow_32 : 8|28@1+ (1,0) [0|268435455] ""  PC
 SG_ BalDchg_PosCellHigh_32 : 36|28@1+ (1,0) [0|268435455] ""  PC

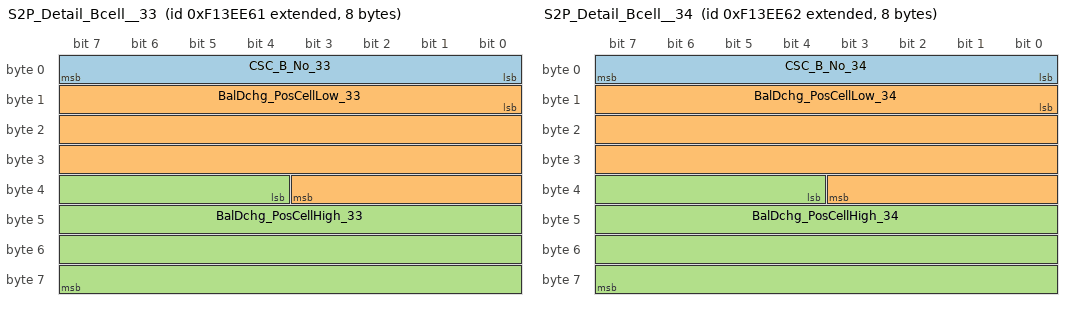
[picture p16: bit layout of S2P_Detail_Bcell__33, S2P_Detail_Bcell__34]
BO_ 2400448097 S2P_Detail_Bcell__33: 8 SBMU
 SG_ CSC_B_No_33 : 0|8@1+ (1,0) [0|255] ""  PC
 SG_ BalDchg_PosCellLow_33 : 8|28@1+ (1,0) [0|268435455] ""  PC
 SG_ BalDchg_PosCellHigh_33 : 36|28@1+ (1,0) [0|268435455] ""  PC

BO_ 2400448098 S2P_Detail_Bcell__34: 8 SBMU
 SG_ CSC_B_No_34 : 0|8@1+ (1,0) [0|255] ""  PC
 SG_ BalDchg_PosCellLow_34 : 8|28@1+ (1,0) [0|268435455] ""  PC
 SG_ BalDchg_PosCellHigh_34 : 36|28@1+ (1,0) [0|268435455] ""  PC

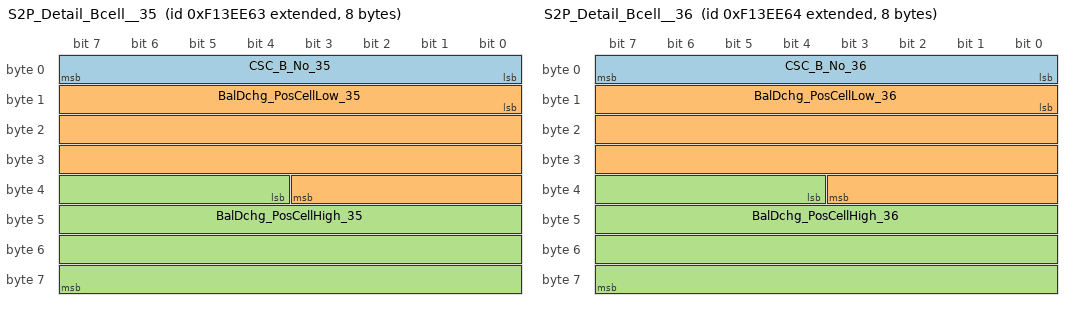
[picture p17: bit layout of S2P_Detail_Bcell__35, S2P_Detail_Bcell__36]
BO_ 2400448099 S2P_Detail_Bcell__35: 8 SBMU
 SG_ CSC_B_No_35 : 0|8@1+ (1,0) [0|255] ""  PC
 SG_ BalDchg_PosCellLow_35 : 8|28@1+ (1,0) [0|268435455] ""  PC
 SG_ BalDchg_PosCellHigh_35 : 36|28@1+ (1,0) [0|268435455] ""  PC

BO_ 2400448100 S2P_Detail_Bcell__36: 8 SBMU
 SG_ CSC_B_No_36 : 0|8@1+ (1,0) [0|255] ""  PC
 SG_ BalDchg_PosCellLow_36 : 8|28@1+ (1,0) [0|268435455] ""  PC
 SG_ BalDchg_PosCellHigh_36 : 36|28@1+ (1,0) [0|268435455] ""  PC

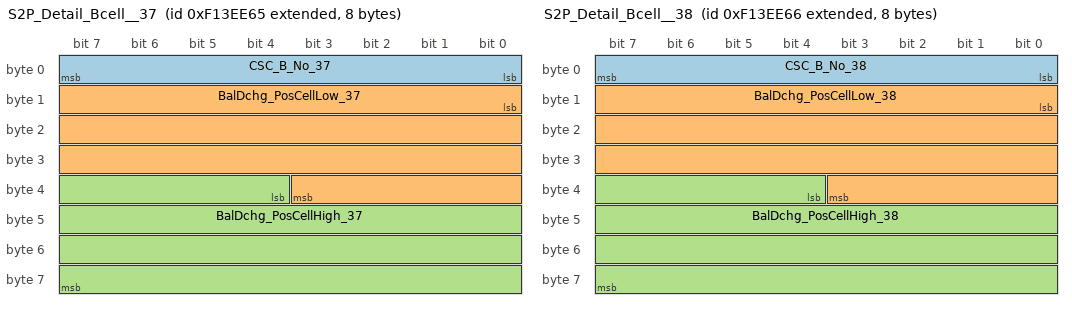
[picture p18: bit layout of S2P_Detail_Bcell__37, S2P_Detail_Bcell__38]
BO_ 2400448101 S2P_Detail_Bcell__37: 8 SBMU
 SG_ CSC_B_No_37 : 0|8@1+ (1,0) [0|255] ""  PC
 SG_ BalDchg_PosCellLow_37 : 8|28@1+ (1,0) [0|268435455] ""  PC
 SG_ BalDchg_PosCellHigh_37 : 36|28@1+ (1,0) [0|268435455] ""  PC

BO_ 2400448102 S2P_Detail_Bcell__38: 8 SBMU
 SG_ CSC_B_No_38 : 0|8@1+ (1,0) [0|255] ""  PC
 SG_ BalDchg_PosCellLow_38 : 8|28@1+ (1,0) [0|268435455] ""  PC
 SG_ BalDchg_PosCellHigh_38 : 36|28@1+ (1,0) [0|268435455] ""  PC

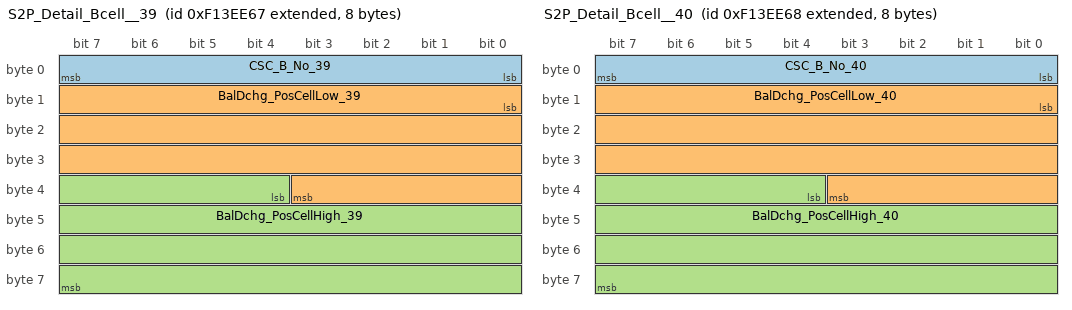
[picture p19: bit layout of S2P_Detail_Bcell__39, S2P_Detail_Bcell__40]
BO_ 2400448103 S2P_Detail_Bcell__39: 8 SBMU
 SG_ CSC_B_No_39 : 0|8@1+ (1,0) [0|255] ""  PC
 SG_ BalDchg_PosCellLow_39 : 8|28@1+ (1,0) [0|268435455] ""  PC
 SG_ BalDchg_PosCellHigh_39 : 36|28@1+ (1,0) [0|268435455] ""  PC

BO_ 2400448104 S2P_Detail_Bcell__40: 8 SBMU
 SG_ CSC_B_No_40 : 0|8@1+ (1,0) [0|255] ""  PC
 SG_ BalDchg_PosCellLow_40 : 8|28@1+ (1,0) [0|268435455] ""  PC
 SG_ BalDchg_PosCellHigh_40 : 36|28@1+ (1,0) [0|268435455] ""  PC

BO_ 2400448105 S2P_Detail_Bcell__41: 8 SBMU
 SG_ CSC_B_No_41 : 0|8@1+ (1,0) [0|255] ""  PC
 SG_ BalDchg_PosCellLow_41 : 8|28@1+ (1,0) [0|268435455] ""  PC
 SG_ BalDchg_PosCellHigh_41 : 36|28@1+ (1,0) [0|268435455] ""  PC

BO_ 2400448106 S2P_Detail_Bcell__42: 8 SBMU
 SG_ CSC_B_No_42 : 0|8@1+ (1,0) [0|255] ""  PC
 SG_ BalDchg_PosCellLow_42 : 8|28@1+ (1,0) [0|268435455] ""  PC
 SG_ BalDchg_PosCellHigh_42 : 36|28@1+ (1,0) [0|268435455] ""  PC

BO_ 2400448107 S2P_Detail_Bcell__43: 8 SBMU
 SG_ CSC_B_No_43 : 0|8@1+ (1,0) [0|255] ""  PC
 SG_ BalDchg_PosCellLow_43 : 8|28@1+ (1,0) [0|268435455] ""  PC
 SG_ BalDchg_PosCellHigh_43 : 36|28@1+ (1,0) [0|268435455] ""  PC

BO_ 2400448108 S2P_Detail_Bcell__44: 8 SBMU
 SG_ CSC_B_No_44 : 0|8@1+ (1,0) [0|255] ""  PC
 SG_ BalDchg_PosCellLow_44 : 8|28@1+ (1,0) [0|268435455] ""  PC
 SG_ BalDchg_PosCellHigh_44 : 36|28@1+ (1,0) [0|268435455] ""  PC

BO_ 2400448109 S2P_Detail_Bcell__45: 8 SBMU
 SG_ CSC_B_No_45 : 0|8@1+ (1,0) [0|255] ""  PC
 SG_ BalDchg_PosCellLow_45 : 8|28@1+ (1,0) [0|268435455] ""  PC
 SG_ BalDchg_PosCellHigh_45 : 36|28@1+ (1,0) [0|268435455] ""  PC

BO_ 2400448110 S2P_Detail_Bcell__46: 8 SBMU
 SG_ CSC_B_No_46 : 0|8@1+ (1,0) [0|255] ""  PC
 SG_ BalDchg_PosCellLow_46 : 8|28@1+ (1,0) [0|268435455] ""  PC
 SG_ BalDchg_PosCellHigh_46 : 36|28@1+ (1,0) [0|268435455] ""  PC

BO_ 2400448111 S2P_Detail_Bcell__47: 8 SBMU
 SG_ CSC_B_No_47 : 0|8@1+ (1,0) [0|255] ""  PC
 SG_ BalDchg_PosCellLow_47 : 8|28@1+ (1,0) [0|268435455] ""  PC
 SG_ BalDchg_PosCellHigh_47 : 36|28@1+ (1,0) [0|268435455] ""  PC

BO_ 2400448112 S2P_Detail_Bcell__48: 8 SBMU
 SG_ CSC_B_No_48 : 0|8@1+ (1,0) [0|255] ""  PC
 SG_ BalDchg_PosCellLow_48 : 8|28@1+ (1,0) [0|268435455] ""  PC
 SG_ BalDchg_PosCellHigh_48 : 36|28@1+ (1,0) [0|268435455] ""  PC

BO_ 2400448113 S2P_Detail_Bcell__49: 8 SBMU
 SG_ CSC_B_No_49 : 0|8@1+ (1,0) [0|255] ""  PC
 SG_ BalDchg_PosCellLow_49 : 8|28@1+ (1,0) [0|268435455] ""  PC
 SG_ BalDchg_PosCellHigh_49 : 36|28@1+ (1,0) [0|268435455] ""  PC

BO_ 2400448114 S2P_Detail_Bcell__50: 8 SBMU
 SG_ CSC_B_No_50 : 0|8@1+ (1,0) [0|255] ""  PC
 SG_ BalDchg_PosCellLow_50 : 8|28@1+ (1,0) [0|268435455] ""  PC
 SG_ BalDchg_PosCellHigh_50 : 36|28@1+ (1,0) [0|268435455] ""  PC

BO_ 2400448115 S2P_Detail_Bcell__51: 8 SBMU
 SG_ CSC_B_No_51 : 0|8@1+ (1,0) [0|255] ""  PC
 SG_ BalDchg_PosCellLow_51 : 8|28@1+ (1,0) [0|268435455] ""  PC
 SG_ BalDchg_PosCellHigh_51 : 36|28@1+ (1,0) [0|268435455] ""  PC

BO_ 2400448116 S2P_Detail_Bcell__52: 8 SBMU
 SG_ CSC_B_No_52 : 0|8@1+ (1,0) [0|255] ""  PC
 SG_ BalDchg_PosCellLow_52 : 8|28@1+ (1,0) [0|268435455] ""  PC
 SG_ BalDchg_PosCellHigh_52 : 36|28@1+ (1,0) [0|268435455] ""  PC

BO_ 2400448117 S2P_Detail_Bcell__53: 8 SBMU
 SG_ CSC_B_No_53 : 0|8@1+ (1,0) [0|255] ""  PC
 SG_ BalDchg_PosCellLow_53 : 8|28@1+ (1,0) [0|268435455] ""  PC
 SG_ BalDchg_PosCellHigh_53 : 36|28@1+ (1,0) [0|268435455] ""  PC

BO_ 2400448118 S2P_Detail_Bcell__54: 8 SBMU
 SG_ CSC_B_No_54 : 0|8@1+ (1,0) [0|255] ""  PC
 SG_ BalDchg_PosCellLow_54 : 8|28@1+ (1,0) [0|268435455] ""  PC
 SG_ BalDchg_PosCellHigh_54 : 36|28@1+ (1,0) [0|268435455] ""  PC

BO_ 2400448119 S2P_Detail_Bcell__55: 8 SBMU
 SG_ CSC_B_No_55 : 0|8@1+ (1,0) [0|255] ""  PC
 SG_ BalDchg_PosCellLow_55 : 8|28@1+ (1,0) [0|268435455] ""  PC
 SG_ BalDchg_PosCellHigh_55 : 36|28@1+ (1,0) [0|268435455] ""  PC

BO_ 2400448120 S2P_Detail_Bcell__56: 8 SBMU
 SG_ CSC_B_No_56 : 0|8@1+ (1,0) [0|255] ""  PC
 SG_ BalDchg_PosCellLow_56 : 8|28@1+ (1,0) [0|268435455] ""  PC
 SG_ BalDchg_PosCellHigh_56 : 36|28@1+ (1,0) [0|268435455] ""  PC

BO_ 2400448121 S2P_Detail_Bcell__57: 8 SBMU
 SG_ CSC_B_No_57 : 0|8@1+ (1,0) [0|255] ""  PC
 SG_ BalDchg_PosCellLow_57 : 8|28@1+ (1,0) [0|268435455] ""  PC
 SG_ BalDchg_PosCellHigh_57 : 36|28@1+ (1,0) [0|268435455] ""  PC

BO_ 2400448122 S2P_Detail_Bcell__58: 8 SBMU
 SG_ CSC_B_No_58 : 0|8@1+ (1,0) [0|255] ""  PC
 SG_ BalDchg_PosCellLow_58 : 8|28@1+ (1,0) [0|268435455] ""  PC
 SG_ BalDchg_PosCellHigh_58 : 36|28@1+ (1,0) [0|268435455] ""  PC

BO_ 2400448123 S2P_Detail_Bcell__59: 8 SBMU
 SG_ CSC_B_No_59 : 0|8@1+ (1,0) [0|255] ""  PC
 SG_ BalDchg_PosCellLow_59 : 8|28@1+ (1,0) [0|268435455] ""  PC
 SG_ BalDchg_PosCellHigh_59 : 36|28@1+ (1,0) [0|268435455] ""  PC

BO_ 2400448124 S2P_Detail_Bcell__60: 8 SBMU
 SG_ CSC_B_No_60 : 0|8@1+ (1,0) [0|255] ""  PC
 SG_ BalDchg_PosCellLow_60 : 8|28@1+ (1,0) [0|268435455] ""  PC
 SG_ BalDchg_PosCellHigh_60 : 36|28@1+ (1,0) [0|268435455] ""  PC

BO_ 2400448125 S2P_Detail_Bcell__61: 8 SBMU
 SG_ CSC_B_No_61 : 0|8@1+ (1,0) [0|255] ""  PC
 SG_ BalDchg_PosCellLow_61 : 8|28@1+ (1,0) [0|268435455] ""  PC
 SG_ BalDchg_PosCellHigh_61 : 36|28@1+ (1,0) [0|268435455] ""  PC

BO_ 2400448126 S2P_Detail_Bcell__62: 8 SBMU
 SG_ CSC_B_No_62 : 0|8@1+ (1,0) [0|255] ""  PC
 SG_ BalDchg_PosCellLow_62 : 8|28@1+ (1,0) [0|268435455] ""  PC
 SG_ BalDchg_PosCellHigh_62 : 36|28@1+ (1,0) [0|268435455] ""  PC

BO_ 2400448127 S2P_Detail_Bcell__63: 8 SBMU
 SG_ CSC_B_No_63 : 0|8@1+ (1,0) [0|255] ""  PC
 SG_ BalDchg_PosCellLow_63 : 8|28@1+ (1,0) [0|268435455] ""  PC
 SG_ BalDchg_PosCellHigh_63 : 36|28@1+ (1,0) [0|268435455] ""  PC

BO_ 2400579137 S2P_Detail_BStatus__01: 8 SBMU
 SG_ CSC_B_S_No_01 : 0|8@1+ (1,0) [0|255] ""  PC
 SG_ State_Balance_Status_01 : 8|4@1+ (1,0) [0|15] ""  PC
 SG_ State_Balance_Fault_01 : 12|1@1+ (1,0) [0|1] ""  PC

BO_ 2400579138 S2P_Detail_BStatus__02: 8 SBMU
 SG_ CSC_B_S_No_02 : 0|8@1+ (1,0) [0|255] ""  PC
 SG_ State_Balance_Status_02 : 8|4@1+ (1,0) [0|15] ""  PC
 SG_ State_Balance_Fault_02 : 12|1@1+ (1,0) [0|1] ""  PC

BO_ 2400579139 S2P_Detail_BStatus__03: 8 SBMU
 SG_ CSC_B_S_No_03 : 0|8@1+ (1,0) [0|255] ""  PC
 SG_ State_Balance_Status_03 : 8|4@1+ (1,0) [0|15] ""  PC
 SG_ State_Balance_Fault_03 : 12|1@1+ (1,0) [0|1] ""  PC

BO_ 2400579140 S2P_Detail_BStatus__04: 8 SBMU
 SG_ CSC_B_S_No_04 : 0|8@1+ (1,0) [0|255] ""  PC
 SG_ State_Balance_Status_04 : 8|4@1+ (1,0) [0|15] ""  PC
 SG_ State_Balance_Fault_04 : 12|1@1+ (1,0) [0|1] ""  PC

BO_ 2400579141 S2P_Detail_BStatus__05: 8 SBMU
 SG_ CSC_B_S_No_05 : 0|8@1+ (1,0) [0|255] ""  PC
 SG_ State_Balance_Status_05 : 8|4@1+ (1,0) [0|15] ""  PC
 SG_ State_Balance_Fault_05 : 12|1@1+ (1,0) [0|1] ""  PC

BO_ 2400579142 S2P_Detail_BStatus__06: 8 SBMU
 SG_ CSC_B_S_No_06 : 0|8@1+ (1,0) [0|255] ""  PC
 SG_ State_Balance_Status_06 : 8|4@1+ (1,0) [0|15] ""  PC
 SG_ State_Balance_Fault_06 : 12|1@1+ (1,0) [0|1] ""  PC

BO_ 2400579143 S2P_Detail_BStatus__07: 8 SBMU
 SG_ CSC_B_S_No_07 : 0|8@1+ (1,0) [0|255] ""  PC
 SG_ State_Balance_Status_07 : 8|4@1+ (1,0) [0|15] ""  PC
 SG_ State_Balance_Fault_07 : 12|1@1+ (1,0) [0|1] ""  PC

BO_ 2400579144 S2P_Detail_BStatus__08: 8 SBMU
 SG_ CSC_B_S_No_08 : 0|8@1+ (1,0) [0|255] ""  PC
 SG_ State_Balance_Status_08 : 8|4@1+ (1,0) [0|15] ""  PC
 SG_ State_Balance_Fault_08 : 12|1@1+ (1,0) [0|1] ""  PC

BO_ 2400579145 S2P_Detail_BStatus__09: 8 SBMU
 SG_ CSC_B_S_No_09 : 0|8@1+ (1,0) [0|255] ""  PC
 SG_ State_Balance_Status_09 : 8|4@1+ (1,0) [0|15] ""  PC
 SG_ State_Balance_Fault_09 : 12|1@1+ (1,0) [0|1] ""  PC

BO_ 2400579146 S2P_Detail_BStatus__10: 8 SBMU
 SG_ CSC_B_S_No_10 : 0|8@1+ (1,0) [0|255] ""  PC
 SG_ State_Balance_Status_10 : 8|4@1+ (1,0) [0|15] ""  PC
 SG_ State_Balance_Fault_10 : 12|1@1+ (1,0) [0|1] ""  PC

BO_ 2400579147 S2P_Detail_BStatus__11: 8 SBMU
 SG_ CSC_B_S_No_11 : 0|8@1+ (1,0) [0|255] ""  PC
 SG_ State_Balance_Status_11 : 8|4@1+ (1,0) [0|15] ""  PC
 SG_ State_Balance_Fault_11 : 12|1@1+ (1,0) [0|1] ""  PC

BO_ 2400579148 S2P_Detail_BStatus__12: 8 SBMU
 SG_ CSC_B_S_No_12 : 0|8@1+ (1,0) [0|255] ""  PC
 SG_ State_Balance_Status_12 : 8|4@1+ (1,0) [0|15] ""  PC
 SG_ State_Balance_Fault_12 : 12|1@1+ (1,0) [0|1] ""  PC

BO_ 2400579149 S2P_Detail_BStatus__13: 8 SBMU
 SG_ CSC_B_S_No_13 : 0|8@1+ (1,0) [0|255] ""  PC
 SG_ State_Balance_Status_13 : 8|4@1+ (1,0) [0|15] ""  PC
 SG_ State_Balance_Fault_13 : 12|1@1+ (1,0) [0|1] ""  PC

BO_ 2400579150 S2P_Detail_BStatus__14: 8 SBMU
 SG_ CSC_B_S_No_14 : 0|8@1+ (1,0) [0|255] ""  PC
 SG_ State_Balance_Status_14 : 8|4@1+ (1,0) [0|15] ""  PC
 SG_ State_Balance_Fault_14 : 12|1@1+ (1,0) [0|1] ""  PC

BO_ 2400579151 S2P_Detail_BStatus__15: 8 SBMU
 SG_ CSC_B_S_No_15 : 0|8@1+ (1,0) [0|255] ""  PC
 SG_ State_Balance_Status_15 : 8|4@1+ (1,0) [0|15] ""  PC
 SG_ State_Balance_Fault_15 : 12|1@1+ (1,0) [0|1] ""  PC

BO_ 2400579152 S2P_Detail_BStatus__16: 8 SBMU
 SG_ CSC_B_S_No_16 : 0|8@1+ (1,0) [0|255] ""  PC
 SG_ State_Balance_Status_16 : 8|4@1+ (1,0) [0|15] ""  PC
 SG_ State_Balance_Fault_16 : 12|1@1+ (1,0) [0|1] ""  PC

BO_ 2400579153 S2P_Detail_BStatus__17: 8 SBMU
 SG_ CSC_B_S_No_17 : 0|8@1+ (1,0) [0|255] ""  PC
 SG_ State_Balance_Status_17 : 8|4@1+ (1,0) [0|15] ""  PC
 SG_ State_Balance_Fault_17 : 12|1@1+ (1,0) [0|1] ""  PC

BO_ 2400579154 S2P_Detail_BStatus__18: 8 SBMU
 SG_ CSC_B_S_No_18 : 0|8@1+ (1,0) [0|255] ""  PC
 SG_ State_Balance_Status_18 : 8|4@1+ (1,0) [0|15] ""  PC
 SG_ State_Balance_Fault_18 : 12|1@1+ (1,0) [0|1] ""  PC

BO_ 2400579155 S2P_Detail_BStatus__19: 8 SBMU
 SG_ CSC_B_S_No_19 : 0|8@1+ (1,0) [0|255] ""  PC
 SG_ State_Balance_Status_19 : 8|4@1+ (1,0) [0|15] ""  PC
 SG_ State_Balance_Fault_19 : 12|1@1+ (1,0) [0|1] ""  PC

BO_ 2400579156 S2P_Detail_BStatus__20: 8 SBMU
 SG_ CSC_B_S_No_20 : 0|8@1+ (1,0) [0|255] ""  PC
 SG_ State_Balance_Status_20 : 8|4@1+ (1,0) [0|15] ""  PC
 SG_ State_Balance_Fault_20 : 12|1@1+ (1,0) [0|1] ""  PC

BO_ 2400579157 S2P_Detail_BStatus__21: 8 SBMU
 SG_ CSC_B_S_No_21 : 0|8@1+ (1,0) [0|255] ""  PC
 SG_ State_Balance_Status_21 : 8|4@1+ (1,0) [0|15] ""  PC
 SG_ State_Balance_Fault_21 : 12|1@1+ (1,0) [0|1] ""  PC

BO_ 2400579158 S2P_Detail_BStatus__22: 8 SBMU
 SG_ CSC_B_S_No_22 : 0|8@1+ (1,0) [0|255] ""  PC
 SG_ State_Balance_Status_22 : 8|4@1+ (1,0) [0|15] ""  PC
 SG_ State_Balance_Fault_22 : 12|1@1+ (1,0) [0|1] ""  PC

BO_ 2400579159 S2P_Detail_BStatus__23: 8 SBMU
 SG_ CSC_B_S_No_23 : 0|8@1+ (1,0) [0|255] ""  PC
 SG_ State_Balance_Status_23 : 8|4@1+ (1,0) [0|15] ""  PC
 SG_ State_Balance_Fault_23 : 12|1@1+ (1,0) [0|1] ""  PC

BO_ 2400579160 S2P_Detail_BStatus__24: 8 SBMU
 SG_ CSC_B_S_No_24 : 0|8@1+ (1,0) [0|255] ""  PC
 SG_ State_Balance_Status_24 : 8|4@1+ (1,0) [0|15] ""  PC
 SG_ State_Balance_Fault_24 : 12|1@1+ (1,0) [0|1] ""  PC

BO_ 2400579161 S2P_Detail_BStatus__25: 8 SBMU
 SG_ CSC_B_S_No_25 : 0|8@1+ (1,0) [0|255] ""  PC
 SG_ State_Balance_Status_25 : 8|4@1+ (1,0) [0|15] ""  PC
 SG_ State_Balance_Fault_25 : 12|1@1+ (1,0) [0|1] ""  PC

BO_ 2400579162 S2P_Detail_BStatus__26: 8 SBMU
 SG_ CSC_B_S_No_26 : 0|8@1+ (1,0) [0|255] ""  PC
 SG_ State_Balance_Status_26 : 8|4@1+ (1,0) [0|15] ""  PC
 SG_ State_Balance_Fault_26 : 12|1@1+ (1,0) [0|1] ""  PC

BO_ 2400579163 S2P_Detail_BStatus__27: 8 SBMU
 SG_ CSC_B_S_No_27 : 0|8@1+ (1,0) [0|255] ""  PC
 SG_ State_Balance_Status_27 : 8|4@1+ (1,0) [0|15] ""  PC
 SG_ State_Balance_Fault_27 : 12|1@1+ (1,0) [0|1] ""  PC

BO_ 2400579164 S2P_Detail_BStatus__28: 8 SBMU
 SG_ CSC_B_S_No_28 : 0|8@1+ (1,0) [0|255] ""  PC
 SG_ State_Balance_Status_28 : 8|4@1+ (1,0) [0|15] ""  PC
 SG_ State_Balance_Fault_28 : 12|1@1+ (1,0) [0|1] ""  PC

BO_ 2400579165 S2P_Detail_BStatus__29: 8 SBMU
 SG_ CSC_B_S_No_29 : 0|8@1+ (1,0) [0|255] ""  PC
 SG_ State_Balance_Status_29 : 8|4@1+ (1,0) [0|15] ""  PC
 SG_ State_Balance_Fault_29 : 12|1@1+ (1,0) [0|1] ""  PC

BO_ 2400579166 S2P_Detail_BStatus__30: 8 SBMU
 SG_ CSC_B_S_No_30 : 0|8@1+ (1,0) [0|255] ""  PC
 SG_ State_Balance_Status_30 : 8|4@1+ (1,0) [0|15] ""  PC
 SG_ State_Balance_Fault_30 : 12|1@1+ (1,0) [0|1] ""  PC

BO_ 2400579167 S2P_Detail_BStatus__31: 8 SBMU
 SG_ CSC_B_S_No_31 : 0|8@1+ (1,0) [0|255] ""  PC
 SG_ State_Balance_Status_31 : 8|4@1+ (1,0) [0|15] ""  PC
 SG_ State_Balance_Fault_31 : 12|1@1+ (1,0) [0|1] ""  PC

BO_ 2400579168 S2P_Detail_BStatus__32: 8 SBMU
 SG_ CSC_B_S_No_32 : 0|8@1+ (1,0) [0|255] ""  PC
 SG_ State_Balance_Status_32 : 8|4@1+ (1,0) [0|15] ""  PC
 SG_ State_Balance_Fault_32 : 12|1@1+ (1,0) [0|1] ""  PC

BO_ 2400579169 S2P_Detail_BStatus__33: 8 SBMU
 SG_ CSC_B_S_No_33 : 0|8@1+ (1,0) [0|255] ""  PC
 SG_ State_Balance_Status_33 : 8|4@1+ (1,0) [0|15] ""  PC
 SG_ State_Balance_Fault_33 : 12|1@1+ (1,0) [0|1] ""  PC

BO_ 2400579170 S2P_Detail_BStatus__34: 8 SBMU
 SG_ CSC_B_S_No_34 : 0|8@1+ (1,0) [0|255] ""  PC
 SG_ State_Balance_Status_34 : 8|4@1+ (1,0) [0|15] ""  PC
 SG_ State_Balance_Fault_34 : 12|1@1+ (1,0) [0|1] ""  PC

BO_ 2400579171 S2P_Detail_BStatus__35: 8 SBMU
 SG_ CSC_B_S_No_35 : 0|8@1+ (1,0) [0|255] ""  PC
 SG_ State_Balance_Status_35 : 8|4@1+ (1,0) [0|15] ""  PC
 SG_ State_Balance_Fault_35 : 12|1@1+ (1,0) [0|1] ""  PC

BO_ 2400579172 S2P_Detail_BStatus__36: 8 SBMU
 SG_ CSC_B_S_No_36 : 0|8@1+ (1,0) [0|255] ""  PC
 SG_ State_Balance_Status_36 : 8|4@1+ (1,0) [0|15] ""  PC
 SG_ State_Balance_Fault_36 : 12|1@1+ (1,0) [0|1] ""  PC

BO_ 2400579173 S2P_Detail_BStatus__37: 8 SBMU
 SG_ CSC_B_S_No_37 : 0|8@1+ (1,0) [0|255] ""  PC
 SG_ State_Balance_Status_37 : 8|4@1+ (1,0) [0|15] ""  PC
 SG_ State_Balance_Fault_37 : 12|1@1+ (1,0) [0|1] ""  PC

BO_ 2400579174 S2P_Detail_BStatus__38: 8 SBMU
 SG_ CSC_B_S_No_38 : 0|8@1+ (1,0) [0|255] ""  PC
 SG_ State_Balance_Status_38 : 8|4@1+ (1,0) [0|15] ""  PC
 SG_ State_Balance_Fault_38 : 12|1@1+ (1,0) [0|1] ""  PC

BO_ 2400579175 S2P_Detail_BStatus__39: 8 SBMU
 SG_ CSC_B_S_No_39 : 0|8@1+ (1,0) [0|255] ""  PC
 SG_ State_Balance_Status_39 : 8|4@1+ (1,0) [0|15] ""  PC
 SG_ State_Balance_Fault_39 : 12|1@1+ (1,0) [0|1] ""  PC

BO_ 2400579176 S2P_Detail_BStatus__40: 8 SBMU
 SG_ CSC_B_S_No_40 : 0|8@1+ (1,0) [0|255] ""  PC
 SG_ State_Balance_Status_40 : 8|4@1+ (1,0) [0|15] ""  PC
 SG_ State_Balance_Fault_40 : 12|1@1+ (1,0) [0|1] ""  PC

BO_ 2400579177 S2P_Detail_BStatus__41: 8 SBMU
 SG_ CSC_B_S_No_41 : 0|8@1+ (1,0) [0|255] ""  PC
 SG_ State_Balance_Status_41 : 8|4@1+ (1,0) [0|15] ""  PC
 SG_ State_Balance_Fault_41 : 12|1@1+ (1,0) [0|1] ""  PC

BO_ 2400579178 S2P_Detail_BStatus__42: 8 SBMU
 SG_ CSC_B_S_No_42 : 0|8@1+ (1,0) [0|255] ""  PC
 SG_ State_Balance_Status_42 : 8|4@1+ (1,0) [0|15] ""  PC
 SG_ State_Balance_Fault_42 : 12|1@1+ (1,0) [0|1] ""  PC

BO_ 2400579179 S2P_Detail_BStatus__43: 8 SBMU
 SG_ CSC_B_S_No_43 : 0|8@1+ (1,0) [0|255] ""  PC
 SG_ State_Balance_Status_43 : 8|4@1+ (1,0) [0|15] ""  PC
 SG_ State_Balance_Fault_43 : 12|1@1+ (1,0) [0|1] ""  PC

BO_ 2400579180 S2P_Detail_BStatus__44: 8 SBMU
 SG_ CSC_B_S_No_44 : 0|8@1+ (1,0) [0|255] ""  PC
 SG_ State_Balance_Status_44 : 8|4@1+ (1,0) [0|15] ""  PC
 SG_ State_Balance_Fault_44 : 12|1@1+ (1,0) [0|1] ""  PC

BO_ 2400579181 S2P_Detail_BStatus__45: 8 SBMU
 SG_ CSC_B_S_No_45 : 0|8@1+ (1,0) [0|255] ""  PC
 SG_ State_Balance_Status_45 : 8|4@1+ (1,0) [0|15] ""  PC
 SG_ State_Balance_Fault_45 : 12|1@1+ (1,0) [0|1] ""  PC

BO_ 2400579182 S2P_Detail_BStatus__46: 8 SBMU
 SG_ CSC_B_S_No_46 : 0|8@1+ (1,0) [0|255] ""  PC
 SG_ State_Balance_Status_46 : 8|4@1+ (1,0) [0|15] ""  PC
 SG_ State_Balance_Fault_46 : 12|1@1+ (1,0) [0|1] ""  PC

BO_ 2400579183 S2P_Detail_BStatus__47: 8 SBMU
 SG_ CSC_B_S_No_47 : 0|8@1+ (1,0) [0|255] ""  PC
 SG_ State_Balance_Status_47 : 8|4@1+ (1,0) [0|15] ""  PC
 SG_ State_Balance_Fault_47 : 12|1@1+ (1,0) [0|1] ""  PC

BO_ 2400579184 S2P_Detail_BStatus__48: 8 SBMU
 SG_ CSC_B_S_No_48 : 0|8@1+ (1,0) [0|255] ""  PC
 SG_ State_Balance_Status_48 : 8|4@1+ (1,0) [0|15] ""  PC
 SG_ State_Balance_Fault_48 : 12|1@1+ (1,0) [0|1] ""  PC

BO_ 2400579185 S2P_Detail_BStatus__49: 8 SBMU
 SG_ CSC_B_S_No_49 : 0|8@1+ (1,0) [0|255] ""  PC
 SG_ State_Balance_Status_49 : 8|4@1+ (1,0) [0|15] ""  PC
 SG_ State_Balance_Fault_49 : 12|1@1+ (1,0) [0|1] ""  PC

BO_ 2400579186 S2P_Detail_BStatus__50: 8 SBMU
 SG_ CSC_B_S_No_50 : 0|8@1+ (1,0) [0|255] ""  PC
 SG_ State_Balance_Status_50 : 8|4@1+ (1,0) [0|15] ""  PC
 SG_ State_Balance_Fault_50 : 12|1@1+ (1,0) [0|1] ""  PC

BO_ 2400579187 S2P_Detail_BStatus__51: 8 SBMU
 SG_ CSC_B_S_No_51 : 0|8@1+ (1,0) [0|255] ""  PC
 SG_ State_Balance_Status_51 : 8|4@1+ (1,0) [0|15] ""  PC
 SG_ State_Balance_Fault_51 : 12|1@1+ (1,0) [0|1] ""  PC

BO_ 2400579188 S2P_Detail_BStatus__52: 8 SBMU
 SG_ CSC_B_S_No_52 : 0|8@1+ (1,0) [0|255] ""  PC
 SG_ State_Balance_Status_52 : 8|4@1+ (1,0) [0|15] ""  PC
 SG_ State_Balance_Fault_52 : 12|1@1+ (1,0) [0|1] ""  PC

BO_ 2400579189 S2P_Detail_BStatus__53: 8 SBMU
 SG_ CSC_B_S_No_53 : 0|8@1+ (1,0) [0|255] ""  PC
 SG_ State_Balance_Status_53 : 8|4@1+ (1,0) [0|15] ""  PC
 SG_ State_Balance_Fault_53 : 12|1@1+ (1,0) [0|1] ""  PC

BO_ 2400579190 S2P_Detail_BStatus__54: 8 SBMU
 SG_ CSC_B_S_No_54 : 0|8@1+ (1,0) [0|255] ""  PC
 SG_ State_Balance_Status_54 : 8|4@1+ (1,0) [0|15] ""  PC
 SG_ State_Balance_Fault_54 : 12|1@1+ (1,0) [0|1] ""  PC

BO_ 2400579191 S2P_Detail_BStatus__55: 8 SBMU
 SG_ CSC_B_S_No_55 : 0|8@1+ (1,0) [0|255] ""  PC
 SG_ State_Balance_Status_55 : 8|4@1+ (1,0) [0|15] ""  PC
 SG_ State_Balance_Fault_55 : 12|1@1+ (1,0) [0|1] ""  PC

BO_ 2400579192 S2P_Detail_BStatus__56: 8 SBMU
 SG_ CSC_B_S_No_56 : 0|8@1+ (1,0) [0|255] ""  PC
 SG_ State_Balance_Status_56 : 8|4@1+ (1,0) [0|15] ""  PC
 SG_ State_Balance_Fault_56 : 12|1@1+ (1,0) [0|1] ""  PC

CM_ SG_ 2400382583 CSC_T_No_55 "CSC号";
CM_ SG_ 2400382583 CSC_Tcell_Frame_Index_55 "当前CSC中温度数据帧序号";
CM_ SG_ 2400382583 CSC_Tcell_01_55 "温度01";
CM_ SG_ 2400382583 CSC_Tcell_02_55 "温度02";
CM_ SG_ 2400382583 CSC_Tcell_03_55 "温度03";
CM_ SG_ 2400382583 CSC_Tcell_04_55 "温度04";
CM_ SG_ 2400382583 CSC_Tcell_05_55 "温度05";
CM_ SG_ 2400382583 CSC_Tcell_06_55 "温度06";
CM_ SG_ 2400382583 CSC_Tcell_07_55 "温度07";
CM_ SG_ 2400382583 CSC_Tcell_08_55 "温度08";
CM_ SG_ 2400382583 CSC_Tcell_09_55 "温度09";
CM_ SG_ 2400382583 CSC_Tcell_10_55 "温度10";
CM_ SG_ 2400382583 CSC_Tcell_11_55 "温度11";
CM_ SG_ 2400382583 CSC_Tcell_12_55 "温度12";
CM_ SG_ 2400382583 CSC_Tcell_13_55 "温度13";
CM_ SG_ 2400382583 CSC_Tcell_14_55 "温度14";
CM_ SG_ 2400382583 CSC_Tcell_15_55 "温度15";
CM_ SG_ 2400382583 CSC_Tcell_16_55 "温度16";
CM_ SG_ 2400382583 CSC_Tcell_17_55 "温度17";
CM_ SG_ 2400382583 CSC_Tcell_18_55 "温度18";
CM_ SG_ 2400382583 CSC_Tcell_19_55 "温度19";
CM_ SG_ 2400382583 CSC_Tcell_20_55 "温度20";
CM_ SG_ 2400382583 CSC_Tcell_21_55 "温度21";
CM_ SG_ 2400382583 CSC_Tcell_22_55 "温度22";
CM_ SG_ 2400382583 CSC_Tcell_23_55 "温度23";
CM_ SG_ 2400382583 CSC_Tcell_24_55 "温度24";
CM_ SG_ 2400382583 CSC_Tcell_25_55 "温度25";
CM_ SG_ 2400382583 CSC_Tcell_26_55 "温度26";
CM_ SG_ 2400382583 CSC_Tcell_27_55 "温度27";
CM_ SG_ 2400382583 CSC_Tcell_28_55 "温度28";
CM_ SG_ 2400382583 CSC_Tcell_29_55 "温度29";
CM_ SG_ 2400382583 CSC_Tcell_30_55 "温度30";
CM_ SG_ 2400382583 CSC_Tcell_31_55 "温度31";
CM_ SG_ 2400382583 CSC_Tcell_32_55 "温度32";
CM_ SG_ 2400382583 CSC_Tcell_33_55 "温度33";
CM_ SG_ 2400382583 CSC_Tcell_34_55 "温度34";
CM_ SG_ 2400382583 CSC_Tcell_35_55 "温度35";
CM_ SG_ 2400382583 CSC_Tcell_36_55 "温度36";
CM_ SG_ 2400382583 CSC_Tcell_37_55 "温度37";
CM_ SG_ 2400382583 CSC_Tcell_38_55 "温度38";
CM_ SG_ 2400382583 CSC_Tcell_39_55 "温度39";
CM_ SG_ 2400382583 CSC_Tcell_40_55 "温度40";
CM_ SG_ 2400382583 CSC_Tcell_41_55 "温度41";
CM_ SG_ 2400382583 CSC_Tcell_42_55 "温度42";
CM_ SG_ 2400382583 CSC_Tcell_43_55 "温度43";
CM_ SG_ 2400382583 CSC_Tcell_44_55 "温度44";
CM_ SG_ 2400382583 CSC_Tcell_45_55 "温度45";
CM_ SG_ 2400382583 CSC_Tcell_46_55 "温度46";
CM_ SG_ 2400382583 CSC_Tcell_47_55 "温度47";
CM_ SG_ 2400382583 CSC_Tcell_48_55 "温度48";
CM_ SG_ 2400382583 CSC_Tcell_49_55 "温度49";
CM_ SG_ 2400382583 CSC_Tcell_50_55 "温度50";
CM_ SG_ 2400382583 CSC_Tcell_51_55 "温度51";
CM_ SG_ 2400382583 CSC_Tcell_52_55 "温度52";
CM_ SG_ 2400382583 CSC_Tcell_53_55 "温度53";
CM_ SG_ 2400382583 CSC_Tcell_54_55 "温度54";
CM_ SG_ 2400382583 CSC_Tcell_55_55 "温度55";
CM_ SG_ 2400382583 CSC_Tcell_56_55 "温度56";
CM_ SG_ 2400382583 CSC_Tcell_57_55 "温度57";
CM_ SG_ 2400382583 CSC_Tcell_58_55 "温度58";
CM_ SG_ 2400382583 CSC_Tcell_59_55 "温度59";
CM_ SG_ 2400382583 CSC_Tcell_60_55 "温度60";
CM_ SG_ 2400382583 CSC_Tcell_61_55 "温度61";
CM_ SG_ 2400382583 CSC_Tcell_62_55 "温度62";
CM_ SG_ 2400382583 CSC_Tcell_63_55 "温度63";
CM_ SG_ 2400382583 CSC_Tcell_64_55 "温度64";
CM_ SG_ 2400382583 CSC_Tcell_65_55 "温度65";
CM_ SG_ 2400382583 CSC_Tcell_66_55 "温度66";
CM_ SG_ 2400382583 CSC_Tcell_67_55 "温度67";
CM_ SG_ 2400382583 CSC_Tcell_68_55 "温度68";
CM_ SG_ 2400382583 CSC_Tcell_69_55 "温度69";
CM_ SG_ 2400382583 CSC_Tcell_70_55 "温度70";
CM_ SG_ 2400382583 CSC_Tcell_71_55 "温度71";
CM_ SG_ 2400382583 CSC_Tcell_72_55 "温度72";
CM_ SG_ 2400382584 CSC_T_No_56 "CSC号";
CM_ SG_ 2400382584 CSC_Tcell_Frame_Index_56 "当前CSC中温度数据帧序号";
CM_ SG_ 2400382584 CSC_Tcell_01_56 "温度01";
CM_ SG_ 2400382584 CSC_Tcell_02_56 "温度02";
CM_ SG_ 2400382584 CSC_Tcell_03_56 "温度03";
CM_ SG_ 2400382584 CSC_Tcell_04_56 "温度04";
CM_ SG_ 2400382584 CSC_Tcell_05_56 "温度05";
CM_ SG_ 2400382584 CSC_Tcell_06_56 "温度06";
CM_ SG_ 2400382584 CSC_Tcell_07_56 "温度07";
CM_ SG_ 2400382584 CSC_Tcell_08_56 "温度08";
CM_ SG_ 2400382584 CSC_Tcell_09_56 "温度09";
CM_ SG_ 2400382584 CSC_Tcell_10_56 "温度10";
CM_ SG_ 2400382584 CSC_Tcell_11_56 "温度11";
CM_ SG_ 2400382584 CSC_Tcell_12_56 "温度12";
CM_ SG_ 2400382584 CSC_Tcell_13_56 "温度13";
CM_ SG_ 2400382584 CSC_Tcell_14_56 "温度14";
CM_ SG_ 2400382584 CSC_Tcell_15_56 "温度15";
CM_ SG_ 2400382584 CSC_Tcell_16_56 "温度16";
CM_ SG_ 2400382584 CSC_Tcell_17_56 "温度17";
CM_ SG_ 2400382584 CSC_Tcell_18_56 "温度18";
CM_ SG_ 2400382584 CSC_Tcell_19_56 "温度19";
CM_ SG_ 2400382584 CSC_Tcell_20_56 "温度20";
CM_ SG_ 2400382584 CSC_Tcell_21_56 "温度21";
CM_ SG_ 2400382584 CSC_Tcell_22_56 "温度22";
CM_ SG_ 2400382584 CSC_Tcell_23_56 "温度23";
CM_ SG_ 2400382584 CSC_Tcell_24_56 "温度24";
CM_ SG_ 2400382584 CSC_Tcell_25_56 "温度25";
CM_ SG_ 2400382584 CSC_Tcell_26_56 "温度26";
CM_ SG_ 2400382584 CSC_Tcell_27_56 "温度27";
CM_ SG_ 2400382584 CSC_Tcell_28_56 "温度28";
CM_ SG_ 2400382584 CSC_Tcell_29_56 "温度29";
CM_ SG_ 2400382584 CSC_Tcell_30_56 "温度30";
CM_ SG_ 2400382584 CSC_Tcell_31_56 "温度31";
CM_ SG_ 2400382584 CSC_Tcell_32_56 "温度32";
CM_ SG_ 2400382584 CSC_Tcell_33_56 "温度33";
CM_ SG_ 2400382584 CSC_Tcell_34_56 "温度34";
CM_ SG_ 2400382584 CSC_Tcell_35_56 "温度35";
CM_ SG_ 2400382584 CSC_Tcell_36_56 "温度36";
CM_ SG_ 2400382584 CSC_Tcell_37_56 "温度37";
CM_ SG_ 2400382584 CSC_Tcell_38_56 "温度38";
CM_ SG_ 2400382584 CSC_Tcell_39_56 "温度39";
CM_ SG_ 2400382584 CSC_Tcell_40_56 "温度40";
CM_ SG_ 2400382584 CSC_Tcell_41_56 "温度41";
CM_ SG_ 2400382584 CSC_Tcell_42_56 "温度42";
CM_ SG_ 2400382584 CSC_Tcell_43_56 "温度43";
CM_ SG_ 2400382584 CSC_Tcell_44_56 "温度44";
CM_ SG_ 2400382584 CSC_Tcell_45_56 "温度45";
CM_ SG_ 2400382584 CSC_Tcell_46_56 "温度46";
CM_ SG_ 2400382584 CSC_Tcell_47_56 "温度47";
CM_ SG_ 2400382584 CSC_Tcell_48_56 "温度48";
CM_ SG_ 2400382584 CSC_Tcell_49_56 "温度49";
CM_ SG_ 2400382584 CSC_Tcell_50_56 "温度50";
CM_ SG_ 2400382584 CSC_Tcell_51_56 "温度51";
CM_ SG_ 2400382584 CSC_Tcell_52_56 "温度52";
CM_ SG_ 2400382584 CSC_Tcell_53_56 "温度53";
CM_ SG_ 2400382584 CSC_Tcell_54_56 "温度54";
CM_ SG_ 2400382584 CSC_Tcell_55_56 "温度55";
CM_ SG_ 2400382584 CSC_Tcell_56_56 "温度56";
CM_ SG_ 2400382584 CSC_Tcell_57_56 "温度57";
CM_ SG_ 2400382584 CSC_Tcell_58_56 "温度58";
CM_ SG_ 2400382584 CSC_Tcell_59_56 "温度59";
CM_ SG_ 2400382584 CSC_Tcell_60_56 "温度60";
CM_ SG_ 2400382584 CSC_Tcell_61_56 "温度61";
CM_ SG_ 2400382584 CSC_Tcell_62_56 "温度62";
CM_ SG_ 2400382584 CSC_Tcell_63_56 "温度63";
CM_ SG_ 2400382584 CSC_Tcell_64_56 "温度64";
CM_ SG_ 2400382584 CSC_Tcell_65_56 "温度65";
CM_ SG_ 2400382584 CSC_Tcell_66_56 "温度66";
CM_ SG_ 2400382584 CSC_Tcell_67_56 "温度67";
CM_ SG_ 2400382584 CSC_Tcell_68_56 "温度68";
CM_ SG_ 2400382584 CSC_Tcell_69_56 "温度69";
CM_ SG_ 2400382584 CSC_Tcell_70_56 "温度70";
CM_ SG_ 2400382584 CSC_Tcell_71_56 "温度71";
CM_ SG_ 2400382584 CSC_Tcell_72_56 "温度72";
CM_ SG_ 2400382585 CSC_T_No_57 "CSC号";
CM_ SG_ 2400382585 CSC_Tcell_Frame_Index_57 "当前CSC中温度数据帧序号";
CM_ SG_ 2400382585 CSC_Tcell_01_57 "温度01";
CM_ SG_ 2400382585 CSC_Tcell_02_57 "温度02";
CM_ SG_ 2400382585 CSC_Tcell_03_57 "温度03";
CM_ SG_ 2400382585 CSC_Tcell_04_57 "温度04";
CM_ SG_ 2400382585 CSC_Tcell_05_57 "温度05";
CM_ SG_ 2400382585 CSC_Tcell_06_57 "温度06";
CM_ SG_ 2400382585 CSC_Tcell_07_57 "温度07";
CM_ SG_ 2400382585 CSC_Tcell_08_57 "温度08";
CM_ SG_ 2400382585 CSC_Tcell_09_57 "温度09";
CM_ SG_ 2400382585 CSC_Tcell_10_57 "温度10";
CM_ SG_ 2400382585 CSC_Tcell_11_57 "温度11";
CM_ SG_ 2400382585 CSC_Tcell_12_57 "温度12";
CM_ SG_ 2400382585 CSC_Tcell_13_57 "温度13";
CM_ SG_ 2400382585 CSC_Tcell_14_57 "温度14";
CM_ SG_ 2400382585 CSC_Tcell_15_57 "温度15";
CM_ SG_ 2400382585 CSC_Tcell_16_57 "温度16";
CM_ SG_ 2400382585 CSC_Tcell_17_57 "温度17";
CM_ SG_ 2400382585 CSC_Tcell_18_57 "温度18";
CM_ SG_ 2400382585 CSC_Tcell_19_57 "温度19";
CM_ SG_ 2400382585 CSC_Tcell_20_57 "温度20";
CM_ SG_ 2400382585 CSC_Tcell_21_57 "温度21";
CM_ SG_ 2400382585 CSC_Tcell_22_57 "温度22";
CM_ SG_ 2400382585 CSC_Tcell_23_57 "温度23";
CM_ SG_ 2400382585 CSC_Tcell_24_57 "温度24";
CM_ SG_ 2400382585 CSC_Tcell_25_57 "温度25";
CM_ SG_ 2400382585 CSC_Tcell_26_57 "温度26";
CM_ SG_ 2400382585 CSC_Tcell_27_57 "温度27";
CM_ SG_ 2400382585 CSC_Tcell_28_57 "温度28";
CM_ SG_ 2400382585 CSC_Tcell_29_57 "温度29";
CM_ SG_ 2400382585 CSC_Tcell_30_57 "温度30";
CM_ SG_ 2400382585 CSC_Tcell_31_57 "温度31";
CM_ SG_ 2400382585 CSC_Tcell_32_57 "温度32";
CM_ SG_ 2400382585 CSC_Tcell_33_57 "温度33";
CM_ SG_ 2400382585 CSC_Tcell_34_57 "温度34";
CM_ SG_ 2400382585 CSC_Tcell_35_57 "温度35";
CM_ SG_ 2400382585 CSC_Tcell_36_57 "温度36";
CM_ SG_ 2400382585 CSC_Tcell_37_57 "温度37";
CM_ SG_ 2400382585 CSC_Tcell_38_57 "温度38";
CM_ SG_ 2400382585 CSC_Tcell_39_57 "温度39";
CM_ SG_ 2400382585 CSC_Tcell_40_57 "温度40";
CM_ SG_ 2400382585 CSC_Tcell_41_57 "温度41";
CM_ SG_ 2400382585 CSC_Tcell_42_57 "温度42";
CM_ SG_ 2400382585 CSC_Tcell_43_57 "温度43";
CM_ SG_ 2400382585 CSC_Tcell_44_57 "温度44";
CM_ SG_ 2400382585 CSC_Tcell_45_57 "温度45";
CM_ SG_ 2400382585 CSC_Tcell_46_57 "温度46";
CM_ SG_ 2400382585 CSC_Tcell_47_57 "温度47";
CM_ SG_ 2400382585 CSC_Tcell_48_57 "温度48";
CM_ SG_ 2400382585 CSC_Tcell_49_57 "温度49";
CM_ SG_ 2400382585 CSC_Tcell_50_57 "温度50";
CM_ SG_ 2400382585 CSC_Tcell_51_57 "温度51";
CM_ SG_ 2400382585 CSC_Tcell_52_57 "温度52";
CM_ SG_ 2400382585 CSC_Tcell_53_57 "温度53";
CM_ SG_ 2400382585 CSC_Tcell_54_57 "温度54";
CM_ SG_ 2400382585 CSC_Tcell_55_57 "温度55";
CM_ SG_ 2400382585 CSC_Tcell_56_57 "温度56";
CM_ SG_ 2400382585 CSC_Tcell_57_57 "温度57";
CM_ SG_ 2400382585 CSC_Tcell_58_57 "温度58";
CM_ SG_ 2400382585 CSC_Tcell_59_57 "温度59";
CM_ SG_ 2400382585 CSC_Tcell_60_57 "温度60";
CM_ SG_ 2400382585 CSC_Tcell_61_57 "温度61";
CM_ SG_ 2400382585 CSC_Tcell_62_57 "温度62";
CM_ SG_ 2400382585 CSC_Tcell_63_57 "温度63";
CM_ SG_ 2400382585 CSC_Tcell_64_57 "温度64";
CM_ SG_ 2400382585 CSC_Tcell_65_57 "温度65";
CM_ SG_ 2400382585 CSC_Tcell_66_57 "温度66";
CM_ SG_ 2400382585 CSC_Tcell_67_57 "温度67";
CM_ SG_ 2400382585 CSC_Tcell_68_57 "温度68";
CM_ SG_ 2400382585 CSC_Tcell_69_57 "温度69";
CM_ SG_ 2400382585 CSC_Tcell_70_57 "温度70";
CM_ SG_ 2400382585 CSC_Tcell_71_57 "温度71";
CM_ SG_ 2400382585 CSC_Tcell_72_57 "温度72";
CM_ SG_ 2400382586 CSC_T_No_58 "CSC号";
CM_ SG_ 2400382586 CSC_Tcell_Frame_Index_58 "当前CSC中温度数据帧序号";
CM_ SG_ 2400382586 CSC_Tcell_01_58 "温度01";
CM_ SG_ 2400382586 CSC_Tcell_02_58 "温度02";
CM_ SG_ 2400382586 CSC_Tcell_03_58 "温度03";
CM_ SG_ 2400382586 CSC_Tcell_04_58 "温度04";
CM_ SG_ 2400382586 CSC_Tcell_05_58 "温度05";
CM_ SG_ 2400382586 CSC_Tcell_06_58 "温度06";
CM_ SG_ 2400382586 CSC_Tcell_07_58 "温度07";
CM_ SG_ 2400382586 CSC_Tcell_08_58 "温度08";
CM_ SG_ 2400382586 CSC_Tcell_09_58 "温度09";
CM_ SG_ 2400382586 CSC_Tcell_10_58 "温度10";
CM_ SG_ 2400382586 CSC_Tcell_11_58 "温度11";
CM_ SG_ 2400382586 CSC_Tcell_12_58 "温度12";
CM_ SG_ 2400382586 CSC_Tcell_13_58 "温度13";
CM_ SG_ 2400382586 CSC_Tcell_14_58 "温度14";
CM_ SG_ 2400382586 CSC_Tcell_15_58 "温度15";
CM_ SG_ 2400382586 CSC_Tcell_16_58 "温度16";
CM_ SG_ 2400382586 CSC_Tcell_17_58 "温度17";
CM_ SG_ 2400382586 CSC_Tcell_18_58 "温度18";
CM_ SG_ 2400382586 CSC_Tcell_19_58 "温度19";
CM_ SG_ 2400382586 CSC_Tcell_20_58 "温度20";
CM_ SG_ 2400382586 CSC_Tcell_21_58 "温度21";
CM_ SG_ 2400382586 CSC_Tcell_22_58 "温度22";
CM_ SG_ 2400382586 CSC_Tcell_23_58 "温度23";
CM_ SG_ 2400382586 CSC_Tcell_24_58 "温度24";
CM_ SG_ 2400382586 CSC_Tcell_25_58 "温度25";
CM_ SG_ 2400382586 CSC_Tcell_26_58 "温度26";
CM_ SG_ 2400382586 CSC_Tcell_27_58 "温度27";
CM_ SG_ 2400382586 CSC_Tcell_28_58 "温度28";
CM_ SG_ 2400382586 CSC_Tcell_29_58 "温度29";
CM_ SG_ 2400382586 CSC_Tcell_30_58 "温度30";
CM_ SG_ 2400382586 CSC_Tcell_31_58 "温度31";
CM_ SG_ 2400382586 CSC_Tcell_32_58 "温度32";
CM_ SG_ 2400382586 CSC_Tcell_33_58 "温度33";
CM_ SG_ 2400382586 CSC_Tcell_34_58 "温度34";
CM_ SG_ 2400382586 CSC_Tcell_35_58 "温度35";
CM_ SG_ 2400382586 CSC_Tcell_36_58 "温度36";
CM_ SG_ 2400382586 CSC_Tcell_37_58 "温度37";
CM_ SG_ 2400382586 CSC_Tcell_38_58 "温度38";
CM_ SG_ 2400382586 CSC_Tcell_39_58 "温度39";
CM_ SG_ 2400382586 CSC_Tcell_40_58 "温度40";
CM_ SG_ 2400382586 CSC_Tcell_41_58 "温度41";
CM_ SG_ 2400382586 CSC_Tcell_42_58 "温度42";
CM_ SG_ 2400382586 CSC_Tcell_43_58 "温度43";
CM_ SG_ 2400382586 CSC_Tcell_44_58 "温度44";
CM_ SG_ 2400382586 CSC_Tcell_45_58 "温度45";
CM_ SG_ 2400382586 CSC_Tcell_46_58 "温度46";
CM_ SG_ 2400382586 CSC_Tcell_47_58 "温度47";
CM_ SG_ 2400382586 CSC_Tcell_48_58 "温度48";
CM_ SG_ 2400382586 CSC_Tcell_49_58 "温度49";
CM_ SG_ 2400382586 CSC_Tcell_50_58 "温度50";
CM_ SG_ 2400382586 CSC_Tcell_51_58 "温度51";
CM_ SG_ 2400382586 CSC_Tcell_52_58 "温度52";
CM_ SG_ 2400382586 CSC_Tcell_53_58 "温度53";
CM_ SG_ 2400382586 CSC_Tcell_54_58 "温度54";
CM_ SG_ 2400382586 CSC_Tcell_55_58 "温度55";
CM_ SG_ 2400382586 CSC_Tcell_56_58 "温度56";
CM_ SG_ 2400382586 CSC_Tcell_57_58 "温度57";
CM_ SG_ 2400382586 CSC_Tcell_58_58 "温度58";
CM_ SG_ 2400382586 CSC_Tcell_59_58 "温度59";
CM_ SG_ 2400382586 CSC_Tcell_60_58 "温度60";
CM_ SG_ 2400382586 CSC_Tcell_61_58 "温度61";
CM_ SG_ 2400382586 CSC_Tcell_62_58 "温度62";
CM_ SG_ 2400382586 CSC_Tcell_63_58 "温度63";
CM_ SG_ 2400382586 CSC_Tcell_64_58 "温度64";
CM_ SG_ 2400382586 CSC_Tcell_65_58 "温度65";
CM_ SG_ 2400382586 CSC_Tcell_66_58 "温度66";
CM_ SG_ 2400382586 CSC_Tcell_67_58 "温度67";
CM_ SG_ 2400382586 CSC_Tcell_68_58 "温度68";
CM_ SG_ 2400382586 CSC_Tcell_69_58 "温度69";
CM_ SG_ 2400382586 CSC_Tcell_70_58 "温度70";
CM_ SG_ 2400382586 CSC_Tcell_71_58 "温度71";
CM_ SG_ 2400382586 CSC_Tcell_72_58 "温度72";
CM_ SG_ 2400382587 CSC_T_No_59 "CSC号";
CM_ SG_ 2400382587 CSC_Tcell_Frame_Index_59 "当前CSC中温度数据帧序号";
CM_ SG_ 2400382587 CSC_Tcell_01_59 "温度01";
CM_ SG_ 2400382587 CSC_Tcell_02_59 "温度02";
CM_ SG_ 2400382587 CSC_Tcell_03_59 "温度03";
CM_ SG_ 2400382587 CSC_Tcell_04_59 "温度04";
CM_ SG_ 2400382587 CSC_Tcell_05_59 "温度05";
CM_ SG_ 2400382587 CSC_Tcell_06_59 "温度06";
CM_ SG_ 2400382587 CSC_Tcell_07_59 "温度07";
CM_ SG_ 2400382587 CSC_Tcell_08_59 "温度08";
CM_ SG_ 2400382587 CSC_Tcell_09_59 "温度09";
CM_ SG_ 2400382587 CSC_Tcell_10_59 "温度10";
CM_ SG_ 2400382587 CSC_Tcell_11_59 "温度11";
CM_ SG_ 2400382587 CSC_Tcell_12_59 "温度12";
CM_ SG_ 2400382587 CSC_Tcell_13_59 "温度13";
CM_ SG_ 2400382587 CSC_Tcell_14_59 "温度14";
CM_ SG_ 2400382587 CSC_Tcell_15_59 "温度15";
CM_ SG_ 2400382587 CSC_Tcell_16_59 "温度16";
CM_ SG_ 2400382587 CSC_Tcell_17_59 "温度17";
CM_ SG_ 2400382587 CSC_Tcell_18_59 "温度18";
CM_ SG_ 2400382587 CSC_Tcell_19_59 "温度19";
CM_ SG_ 2400382587 CSC_Tcell_20_59 "温度20";
CM_ SG_ 2400382587 CSC_Tcell_21_59 "温度21";
CM_ SG_ 2400382587 CSC_Tcell_22_59 "温度22";
CM_ SG_ 2400382587 CSC_Tcell_23_59 "温度23";
CM_ SG_ 2400382587 CSC_Tcell_24_59 "温度24";
CM_ SG_ 2400382587 CSC_Tcell_25_59 "温度25";
CM_ SG_ 2400382587 CSC_Tcell_26_59 "温度26";
CM_ SG_ 2400382587 CSC_Tcell_27_59 "温度27";
CM_ SG_ 2400382587 CSC_Tcell_28_59 "温度28";
CM_ SG_ 2400382587 CSC_Tcell_29_59 "温度29";
CM_ SG_ 2400382587 CSC_Tcell_30_59 "温度30";
CM_ SG_ 2400382587 CSC_Tcell_31_59 "温度31";
CM_ SG_ 2400382587 CSC_Tcell_32_59 "温度32";
CM_ SG_ 2400382587 CSC_Tcell_33_59 "温度33";
CM_ SG_ 2400382587 CSC_Tcell_34_59 "温度34";
CM_ SG_ 2400382587 CSC_Tcell_35_59 "温度35";
CM_ SG_ 2400382587 CSC_Tcell_36_59 "温度36";
CM_ SG_ 2400382587 CSC_Tcell_37_59 "温度37";
CM_ SG_ 2400382587 CSC_Tcell_38_59 "温度38";
CM_ SG_ 2400382587 CSC_Tcell_39_59 "温度39";
CM_ SG_ 2400382587 CSC_Tcell_40_59 "温度40";
CM_ SG_ 2400382587 CSC_Tcell_41_59 "温度41";
CM_ SG_ 2400382587 CSC_Tcell_42_59 "温度42";
CM_ SG_ 2400382587 CSC_Tcell_43_59 "温度43";
CM_ SG_ 2400382587 CSC_Tcell_44_59 "温度44";
CM_ SG_ 2400382587 CSC_Tcell_45_59 "温度45";
CM_ SG_ 2400382587 CSC_Tcell_46_59 "温度46";
CM_ SG_ 2400382587 CSC_Tcell_47_59 "温度47";
CM_ SG_ 2400382587 CSC_Tcell_48_59 "温度48";
CM_ SG_ 2400382587 CSC_Tcell_49_59 "温度49";
CM_ SG_ 2400382587 CSC_Tcell_50_59 "温度50";
CM_ SG_ 2400382587 CSC_Tcell_51_59 "温度51";
CM_ SG_ 2400382587 CSC_Tcell_52_59 "温度52";
CM_ SG_ 2400382587 CSC_Tcell_53_59 "温度53";
CM_ SG_ 2400382587 CSC_Tcell_54_59 "温度54";
CM_ SG_ 2400382587 CSC_Tcell_55_59 "温度55";
CM_ SG_ 2400382587 CSC_Tcell_56_59 "温度56";
CM_ SG_ 2400382587 CSC_Tcell_57_59 "温度57";
CM_ SG_ 2400382587 CSC_Tcell_58_59 "温度58";
CM_ SG_ 2400382587 CSC_Tcell_59_59 "温度59";
CM_ SG_ 2400382587 CSC_Tcell_60_59 "温度60";
CM_ SG_ 2400382587 CSC_Tcell_61_59 "温度61";
CM_ SG_ 2400382587 CSC_Tcell_62_59 "温度62";
CM_ SG_ 2400382587 CSC_Tcell_63_59 "温度63";
CM_ SG_ 2400382587 CSC_Tcell_64_59 "温度64";
CM_ SG_ 2400382587 CSC_Tcell_65_59 "温度65";
CM_ SG_ 2400382587 CSC_Tcell_66_59 "温度66";
CM_ SG_ 2400382587 CSC_Tcell_67_59 "温度67";
CM_ SG_ 2400382587 CSC_Tcell_68_59 "温度68";
CM_ SG_ 2400382587 CSC_Tcell_69_59 "温度69";
CM_ SG_ 2400382587 CSC_Tcell_70_59 "温度70";
CM_ SG_ 2400382587 CSC_Tcell_71_59 "温度71";
CM_ SG_ 2400382587 CSC_Tcell_72_59 "温度72";
CM_ SG_ 2400382588 CSC_T_No_60 "CSC号";
CM_ SG_ 2400382588 CSC_Tcell_Frame_Index_60 "当前CSC中温度数据帧序号";
CM_ SG_ 2400382588 CSC_Tcell_01_60 "温度01";
CM_ SG_ 2400382588 CSC_Tcell_02_60 "温度02";
CM_ SG_ 2400382588 CSC_Tcell_03_60 "温度03";
CM_ SG_ 2400382588 CSC_Tcell_04_60 "温度04";
CM_ SG_ 2400382588 CSC_Tcell_05_60 "温度05";
CM_ SG_ 2400382588 CSC_Tcell_06_60 "温度06";
CM_ SG_ 2400382588 CSC_Tcell_07_60 "温度07";
CM_ SG_ 2400382588 CSC_Tcell_08_60 "温度08";
CM_ SG_ 2400382588 CSC_Tcell_09_60 "温度09";
CM_ SG_ 2400382588 CSC_Tcell_10_60 "温度10";
CM_ SG_ 2400382588 CSC_Tcell_11_60 "温度11";
CM_ SG_ 2400382588 CSC_Tcell_12_60 "温度12";
CM_ SG_ 2400382588 CSC_Tcell_13_60 "温度13";
CM_ SG_ 2400382588 CSC_Tcell_14_60 "温度14";
CM_ SG_ 2400382588 CSC_Tcell_15_60 "温度15";
CM_ SG_ 2400382588 CSC_Tcell_16_60 "温度16";
CM_ SG_ 2400382588 CSC_Tcell_17_60 "温度17";
CM_ SG_ 2400382588 CSC_Tcell_18_60 "温度18";
CM_ SG_ 2400382588 CSC_Tcell_19_60 "温度19";
CM_ SG_ 2400382588 CSC_Tcell_20_60 "温度20";
CM_ SG_ 2400382588 CSC_Tcell_21_60 "温度21";
CM_ SG_ 2400382588 CSC_Tcell_22_60 "温度22";
CM_ SG_ 2400382588 CSC_Tcell_23_60 "温度23";
CM_ SG_ 2400382588 CSC_Tcell_24_60 "温度24";
CM_ SG_ 2400382588 CSC_Tcell_25_60 "温度25";
CM_ SG_ 2400382588 CSC_Tcell_26_60 "温度26";
CM_ SG_ 2400382588 CSC_Tcell_27_60 "温度27";
CM_ SG_ 2400382588 CSC_Tcell_28_60 "温度28";
CM_ SG_ 2400382588 CSC_Tcell_29_60 "温度29";
CM_ SG_ 2400382588 CSC_Tcell_30_60 "温度30";
CM_ SG_ 2400382588 CSC_Tcell_31_60 "温度31";
CM_ SG_ 2400382588 CSC_Tcell_32_60 "温度32";
CM_ SG_ 2400382588 CSC_Tcell_33_60 "温度33";
CM_ SG_ 2400382588 CSC_Tcell_34_60 "温度34";
CM_ SG_ 2400382588 CSC_Tcell_35_60 "温度35";
CM_ SG_ 2400382588 CSC_Tcell_36_60 "温度36";
CM_ SG_ 2400382588 CSC_Tcell_37_60 "温度37";
CM_ SG_ 2400382588 CSC_Tcell_38_60 "温度38";
CM_ SG_ 2400382588 CSC_Tcell_39_60 "温度39";
CM_ SG_ 2400382588 CSC_Tcell_40_60 "温度40";
CM_ SG_ 2400382588 CSC_Tcell_41_60 "温度41";
CM_ SG_ 2400382588 CSC_Tcell_42_60 "温度42";
CM_ SG_ 2400382588 CSC_Tcell_43_60 "温度43";
CM_ SG_ 2400382588 CSC_Tcell_44_60 "温度44";
CM_ SG_ 2400382588 CSC_Tcell_45_60 "温度45";
CM_ SG_ 2400382588 CSC_Tcell_46_60 "温度46";
CM_ SG_ 2400382588 CSC_Tcell_47_60 "温度47";
CM_ SG_ 2400382588 CSC_Tcell_48_60 "温度48";
CM_ SG_ 2400382588 CSC_Tcell_49_60 "温度49";
CM_ SG_ 2400382588 CSC_Tcell_50_60 "温度50";
CM_ SG_ 2400382588 CSC_Tcell_51_60 "温度51";
CM_ SG_ 2400382588 CSC_Tcell_52_60 "温度52";
CM_ SG_ 2400382588 CSC_Tcell_53_60 "温度53";
CM_ SG_ 2400382588 CSC_Tcell_54_60 "温度54";
CM_ SG_ 2400382588 CSC_Tcell_55_60 "温度55";
CM_ SG_ 2400382588 CSC_Tcell_56_60 "温度56";
CM_ SG_ 2400382588 CSC_Tcell_57_60 "温度57";
CM_ SG_ 2400382588 CSC_Tcell_58_60 "温度58";
CM_ SG_ 2400382588 CSC_Tcell_59_60 "温度59";
CM_ SG_ 2400382588 CSC_Tcell_60_60 "温度60";
CM_ SG_ 2400382588 CSC_Tcell_61_60 "温度61";
CM_ SG_ 2400382588 CSC_Tcell_62_60 "温度62";
CM_ SG_ 2400382588 CSC_Tcell_63_60 "温度63";
CM_ SG_ 2400382588 CSC_Tcell_64_60 "温度64";
CM_ SG_ 2400382588 CSC_Tcell_65_60 "温度65";
CM_ SG_ 2400382588 CSC_Tcell_66_60 "温度66";
CM_ SG_ 2400382588 CSC_Tcell_67_60 "温度67";
CM_ SG_ 2400382588 CSC_Tcell_68_60 "温度68";
CM_ SG_ 2400382588 CSC_Tcell_69_60 "温度69";
CM_ SG_ 2400382588 CSC_Tcell_70_60 "温度70";
CM_ SG_ 2400382588 CSC_Tcell_71_60 "温度71";
CM_ SG_ 2400382588 CSC_Tcell_72_60 "温度72";
CM_ SG_ 2400382589 CSC_T_No_61 "CSC号";
CM_ SG_ 2400382589 CSC_Tcell_Frame_Index_61 "当前CSC中温度数据帧序号";
CM_ SG_ 2400382589 CSC_Tcell_01_61 "温度01";
CM_ SG_ 2400382589 CSC_Tcell_02_61 "温度02";
CM_ SG_ 2400382589 CSC_Tcell_03_61 "温度03";
CM_ SG_ 2400382589 CSC_Tcell_04_61 "温度04";
CM_ SG_ 2400382589 CSC_Tcell_05_61 "温度05";
CM_ SG_ 2400382589 CSC_Tcell_06_61 "温度06";
CM_ SG_ 2400382589 CSC_Tcell_07_61 "温度07";
CM_ SG_ 2400382589 CSC_Tcell_08_61 "温度08";
CM_ SG_ 2400382589 CSC_Tcell_09_61 "温度09";
CM_ SG_ 2400382589 CSC_Tcell_10_61 "温度10";
CM_ SG_ 2400382589 CSC_Tcell_11_61 "温度11";
CM_ SG_ 2400382589 CSC_Tcell_12_61 "温度12";
CM_ SG_ 2400382589 CSC_Tcell_13_61 "温度13";
CM_ SG_ 2400382589 CSC_Tcell_14_61 "温度14";
CM_ SG_ 2400382589 CSC_Tcell_15_61 "温度15";
CM_ SG_ 2400382589 CSC_Tcell_16_61 "温度16";
CM_ SG_ 2400382589 CSC_Tcell_17_61 "温度17";
CM_ SG_ 2400382589 CSC_Tcell_18_61 "温度18";
CM_ SG_ 2400382589 CSC_Tcell_19_61 "温度19";
CM_ SG_ 2400382589 CSC_Tcell_20_61 "温度20";
CM_ SG_ 2400382589 CSC_Tcell_21_61 "温度21";
CM_ SG_ 2400382589 CSC_Tcell_22_61 "温度22";
CM_ SG_ 2400382589 CSC_Tcell_23_61 "温度23";
CM_ SG_ 2400382589 CSC_Tcell_24_61 "温度24";
CM_ SG_ 2400382589 CSC_Tcell_25_61 "温度25";
CM_ SG_ 2400382589 CSC_Tcell_26_61 "温度26";
CM_ SG_ 2400382589 CSC_Tcell_27_61 "温度27";
CM_ SG_ 2400382589 CSC_Tcell_28_61 "温度28";
CM_ SG_ 2400382589 CSC_Tcell_29_61 "温度29";
CM_ SG_ 2400382589 CSC_Tcell_30_61 "温度30";
CM_ SG_ 2400382589 CSC_Tcell_31_61 "温度31";
CM_ SG_ 2400382589 CSC_Tcell_32_61 "温度32";
CM_ SG_ 2400382589 CSC_Tcell_33_61 "温度33";
CM_ SG_ 2400382589 CSC_Tcell_34_61 "温度34";
CM_ SG_ 2400382589 CSC_Tcell_35_61 "温度35";
CM_ SG_ 2400382589 CSC_Tcell_36_61 "温度36";
CM_ SG_ 2400382589 CSC_Tcell_37_61 "温度37";
CM_ SG_ 2400382589 CSC_Tcell_38_61 "温度38";
CM_ SG_ 2400382589 CSC_Tcell_39_61 "温度39";
CM_ SG_ 2400382589 CSC_Tcell_40_61 "温度40";
CM_ SG_ 2400382589 CSC_Tcell_41_61 "温度41";
CM_ SG_ 2400382589 CSC_Tcell_42_61 "温度42";
CM_ SG_ 2400382589 CSC_Tcell_43_61 "温度43";
CM_ SG_ 2400382589 CSC_Tcell_44_61 "温度44";
CM_ SG_ 2400382589 CSC_Tcell_45_61 "温度45";
CM_ SG_ 2400382589 CSC_Tcell_46_61 "温度46";
CM_ SG_ 2400382589 CSC_Tcell_47_61 "温度47";
CM_ SG_ 2400382589 CSC_Tcell_48_61 "温度48";
CM_ SG_ 2400382589 CSC_Tcell_49_61 "温度49";
CM_ SG_ 2400382589 CSC_Tcell_50_61 "温度50";
CM_ SG_ 2400382589 CSC_Tcell_51_61 "温度51";
CM_ SG_ 2400382589 CSC_Tcell_52_61 "温度52";
CM_ SG_ 2400382589 CSC_Tcell_53_61 "温度53";
CM_ SG_ 2400382589 CSC_Tcell_54_61 "温度54";
CM_ SG_ 2400382589 CSC_Tcell_55_61 "温度55";
CM_ SG_ 2400382589 CSC_Tcell_56_61 "温度56";
CM_ SG_ 2400382589 CSC_Tcell_57_61 "温度57";
CM_ SG_ 2400382589 CSC_Tcell_58_61 "温度58";
CM_ SG_ 2400382589 CSC_Tcell_59_61 "温度59";
CM_ SG_ 2400382589 CSC_Tcell_60_61 "温度60";
CM_ SG_ 2400382589 CSC_Tcell_61_61 "温度61";
CM_ SG_ 2400382589 CSC_Tcell_62_61 "温度62";
CM_ SG_ 2400382589 CSC_Tcell_63_61 "温度63";
CM_ SG_ 2400382589 CSC_Tcell_64_61 "温度64";
CM_ SG_ 2400382589 CSC_Tcell_65_61 "温度65";
CM_ SG_ 2400382589 CSC_Tcell_66_61 "温度66";
CM_ SG_ 2400382589 CSC_Tcell_67_61 "温度67";
CM_ SG_ 2400382589 CSC_Tcell_68_61 "温度68";
CM_ SG_ 2400382589 CSC_Tcell_69_61 "温度69";
CM_ SG_ 2400382589 CSC_Tcell_70_61 "温度70";
CM_ SG_ 2400382589 CSC_Tcell_71_61 "温度71";
CM_ SG_ 2400382589 CSC_Tcell_72_61 "温度72";
CM_ SG_ 2400382590 CSC_T_No_62 "CSC号";
CM_ SG_ 2400382590 CSC_Tcell_Frame_Index_62 "当前CSC中温度数据帧序号";
CM_ SG_ 2400382590 CSC_Tcell_01_62 "温度01";
CM_ SG_ 2400382590 CSC_Tcell_02_62 "温度02";
CM_ SG_ 2400382590 CSC_Tcell_03_62 "温度03";
CM_ SG_ 2400382590 CSC_Tcell_04_62 "温度04";
CM_ SG_ 2400382590 CSC_Tcell_05_62 "温度05";
CM_ SG_ 2400382590 CSC_Tcell_06_62 "温度06";
CM_ SG_ 2400382590 CSC_Tcell_07_62 "温度07";
CM_ SG_ 2400382590 CSC_Tcell_08_62 "温度08";
CM_ SG_ 2400382590 CSC_Tcell_09_62 "温度09";
CM_ SG_ 2400382590 CSC_Tcell_10_62 "温度10";
CM_ SG_ 2400382590 CSC_Tcell_11_62 "温度11";
CM_ SG_ 2400382590 CSC_Tcell_12_62 "温度12";
CM_ SG_ 2400382590 CSC_Tcell_13_62 "温度13";
CM_ SG_ 2400382590 CSC_Tcell_14_62 "温度14";
CM_ SG_ 2400382590 CSC_Tcell_15_62 "温度15";
CM_ SG_ 2400382590 CSC_Tcell_16_62 "温度16";
CM_ SG_ 2400382590 CSC_Tcell_17_62 "温度17";
CM_ SG_ 2400382590 CSC_Tcell_18_62 "温度18";
CM_ SG_ 2400382590 CSC_Tcell_19_62 "温度19";
CM_ SG_ 2400382590 CSC_Tcell_20_62 "温度20";
CM_ SG_ 2400382590 CSC_Tcell_21_62 "温度21";
CM_ SG_ 2400382590 CSC_Tcell_22_62 "温度22";
CM_ SG_ 2400382590 CSC_Tcell_23_62 "温度23";
CM_ SG_ 2400382590 CSC_Tcell_24_62 "温度24";
CM_ SG_ 2400382590 CSC_Tcell_25_62 "温度25";
CM_ SG_ 2400382590 CSC_Tcell_26_62 "温度26";
CM_ SG_ 2400382590 CSC_Tcell_27_62 "温度27";
CM_ SG_ 2400382590 CSC_Tcell_28_62 "温度28";
CM_ SG_ 2400382590 CSC_Tcell_29_62 "温度29";
CM_ SG_ 2400382590 CSC_Tcell_30_62 "温度30";
CM_ SG_ 2400382590 CSC_Tcell_31_62 "温度31";
CM_ SG_ 2400382590 CSC_Tcell_32_62 "温度32";
CM_ SG_ 2400382590 CSC_Tcell_33_62 "温度33";
CM_ SG_ 2400382590 CSC_Tcell_34_62 "温度34";
CM_ SG_ 2400382590 CSC_Tcell_35_62 "温度35";
CM_ SG_ 2400382590 CSC_Tcell_36_62 "温度36";
CM_ SG_ 2400382590 CSC_Tcell_37_62 "温度37";
CM_ SG_ 2400382590 CSC_Tcell_38_62 "温度38";
CM_ SG_ 2400382590 CSC_Tcell_39_62 "温度39";
CM_ SG_ 2400382590 CSC_Tcell_40_62 "温度40";
CM_ SG_ 2400382590 CSC_Tcell_41_62 "温度41";
CM_ SG_ 2400382590 CSC_Tcell_42_62 "温度42";
CM_ SG_ 2400382590 CSC_Tcell_43_62 "温度43";
CM_ SG_ 2400382590 CSC_Tcell_44_62 "温度44";
CM_ SG_ 2400382590 CSC_Tcell_45_62 "温度45";
CM_ SG_ 2400382590 CSC_Tcell_46_62 "温度46";
CM_ SG_ 2400382590 CSC_Tcell_47_62 "温度47";
CM_ SG_ 2400382590 CSC_Tcell_48_62 "温度48";
CM_ SG_ 2400382590 CSC_Tcell_49_62 "温度49";
CM_ SG_ 2400382590 CSC_Tcell_50_62 "温度50";
CM_ SG_ 2400382590 CSC_Tcell_51_62 "温度51";
CM_ SG_ 2400382590 CSC_Tcell_52_62 "温度52";
CM_ SG_ 2400382590 CSC_Tcell_53_62 "温度53";
CM_ SG_ 2400382590 CSC_Tcell_54_62 "温度54";
CM_ SG_ 2400382590 CSC_Tcell_55_62 "温度55";
CM_ SG_ 2400382590 CSC_Tcell_56_62 "温度56";
CM_ SG_ 2400382590 CSC_Tcell_57_62 "温度57";
CM_ SG_ 2400382590 CSC_Tcell_58_62 "温度58";
CM_ SG_ 2400382590 CSC_Tcell_59_62 "温度59";
CM_ SG_ 2400382590 CSC_Tcell_60_62 "温度60";
CM_ SG_ 2400382590 CSC_Tcell_61_62 "温度61";
CM_ SG_ 2400382590 CSC_Tcell_62_62 "温度62";
CM_ SG_ 2400382590 CSC_Tcell_63_62 "温度63";
CM_ SG_ 2400382590 CSC_Tcell_64_62 "温度64";
CM_ SG_ 2400382590 CSC_Tcell_65_62 "温度65";
CM_ SG_ 2400382590 CSC_Tcell_66_62 "温度66";
CM_ SG_ 2400382590 CSC_Tcell_67_62 "温度67";
CM_ SG_ 2400382590 CSC_Tcell_68_62 "温度68";
CM_ SG_ 2400382590 CSC_Tcell_69_62 "温度69";
CM_ SG_ 2400382590 CSC_Tcell_70_62 "温度70";
CM_ SG_ 2400382590 CSC_Tcell_71_62 "温度71";
CM_ SG_ 2400382590 CSC_Tcell_72_62 "温度72";
CM_ SG_ 2400382591 CSC_T_No_63 "CSC号";
CM_ SG_ 2400382591 CSC_Tcell_Frame_Index_63 "当前CSC中温度数据帧序号";
CM_ SG_ 2400382591 CSC_Tcell_01_63 "温度01";
CM_ SG_ 2400382591 CSC_Tcell_02_63 "温度02";
CM_ SG_ 2400382591 CSC_Tcell_03_63 "温度03";
CM_ SG_ 2400382591 CSC_Tcell_04_63 "温度04";
CM_ SG_ 2400382591 CSC_Tcell_05_63 "温度05";
CM_ SG_ 2400382591 CSC_Tcell_06_63 "温度06";
CM_ SG_ 2400382591 CSC_Tcell_07_63 "温度07";
CM_ SG_ 2400382591 CSC_Tcell_08_63 "温度08";
CM_ SG_ 2400382591 CSC_Tcell_09_63 "温度09";
CM_ SG_ 2400382591 CSC_Tcell_10_63 "温度10";
CM_ SG_ 2400382591 CSC_Tcell_11_63 "温度11";
CM_ SG_ 2400382591 CSC_Tcell_12_63 "温度12";
CM_ SG_ 2400382591 CSC_Tcell_13_63 "温度13";
CM_ SG_ 2400382591 CSC_Tcell_14_63 "温度14";
CM_ SG_ 2400382591 CSC_Tcell_15_63 "温度15";
CM_ SG_ 2400382591 CSC_Tcell_16_63 "温度16";
CM_ SG_ 2400382591 CSC_Tcell_17_63 "温度17";
CM_ SG_ 2400382591 CSC_Tcell_18_63 "温度18";
CM_ SG_ 2400382591 CSC_Tcell_19_63 "温度19";
CM_ SG_ 2400382591 CSC_Tcell_20_63 "温度20";
CM_ SG_ 2400382591 CSC_Tcell_21_63 "温度21";
CM_ SG_ 2400382591 CSC_Tcell_22_63 "温度22";
CM_ SG_ 2400382591 CSC_Tcell_23_63 "温度23";
CM_ SG_ 2400382591 CSC_Tcell_24_63 "温度24";
CM_ SG_ 2400382591 CSC_Tcell_25_63 "温度25";
CM_ SG_ 2400382591 CSC_Tcell_26_63 "温度26";
CM_ SG_ 2400382591 CSC_Tcell_27_63 "温度27";
CM_ SG_ 2400382591 CSC_Tcell_28_63 "温度28";
CM_ SG_ 2400382591 CSC_Tcell_29_63 "温度29";
CM_ SG_ 2400382591 CSC_Tcell_30_63 "温度30";
CM_ SG_ 2400382591 CSC_Tcell_31_63 "温度31";
CM_ SG_ 2400382591 CSC_Tcell_32_63 "温度32";
CM_ SG_ 2400382591 CSC_Tcell_33_63 "温度33";
CM_ SG_ 2400382591 CSC_Tcell_34_63 "温度34";
CM_ SG_ 2400382591 CSC_Tcell_35_63 "温度35";
CM_ SG_ 2400382591 CSC_Tcell_36_63 "温度36";
CM_ SG_ 2400382591 CSC_Tcell_37_63 "温度37";
CM_ SG_ 2400382591 CSC_Tcell_38_63 "温度38";
CM_ SG_ 2400382591 CSC_Tcell_39_63 "温度39";
CM_ SG_ 2400382591 CSC_Tcell_40_63 "温度40";
CM_ SG_ 2400382591 CSC_Tcell_41_63 "温度41";
CM_ SG_ 2400382591 CSC_Tcell_42_63 "温度42";
CM_ SG_ 2400382591 CSC_Tcell_43_63 "温度43";
CM_ SG_ 2400382591 CSC_Tcell_44_63 "温度44";
CM_ SG_ 2400382591 CSC_Tcell_45_63 "温度45";
CM_ SG_ 2400382591 CSC_Tcell_46_63 "温度46";
CM_ SG_ 2400382591 CSC_Tcell_47_63 "温度47";
CM_ SG_ 2400382591 CSC_Tcell_48_63 "温度48";
CM_ SG_ 2400382591 CSC_Tcell_49_63 "温度49";
CM_ SG_ 2400382591 CSC_Tcell_50_63 "温度50";
CM_ SG_ 2400382591 CSC_Tcell_51_63 "温度51";
CM_ SG_ 2400382591 CSC_Tcell_52_63 "温度52";
CM_ SG_ 2400382591 CSC_Tcell_53_63 "温度53";
CM_ SG_ 2400382591 CSC_Tcell_54_63 "温度54";
CM_ SG_ 2400382591 CSC_Tcell_55_63 "温度55";
CM_ SG_ 2400382591 CSC_Tcell_56_63 "温度56";
CM_ SG_ 2400382591 CSC_Tcell_57_63 "温度57";
CM_ SG_ 2400382591 CSC_Tcell_58_63 "温度58";
CM_ SG_ 2400382591 CSC_Tcell_59_63 "温度59";
CM_ SG_ 2400382591 CSC_Tcell_60_63 "温度60";
CM_ SG_ 2400382591 CSC_Tcell_61_63 "温度61";
CM_ SG_ 2400382591 CSC_Tcell_62_63 "温度62";
CM_ SG_ 2400382591 CSC_Tcell_63_63 "温度63";
CM_ SG_ 2400382591 CSC_Tcell_64_63 "温度64";
CM_ SG_ 2400382591 CSC_Tcell_65_63 "温度65";
CM_ SG_ 2400382591 CSC_Tcell_66_63 "温度66";
CM_ SG_ 2400382591 CSC_Tcell_67_63 "温度67";
CM_ SG_ 2400382591 CSC_Tcell_68_63 "温度68";
CM_ SG_ 2400382591 CSC_Tcell_69_63 "温度69";
CM_ SG_ 2400382591 CSC_Tcell_70_63 "温度70";
CM_ SG_ 2400382591 CSC_Tcell_71_63 "温度71";
CM_ SG_ 2400382591 CSC_Tcell_72_63 "温度72";
CM_ SG_ 2400448065 CSC_B_No_01 "CSC号";
CM_ SG_ 2400448065 BalDchg_PosCellLow_01 "放电均衡电芯位置_(按bit)";
CM_ SG_ 2400448065 BalDchg_PosCellHigh_01 "放电均衡电芯位置_(按bit)";
CM_ SG_ 2400448066 CSC_B_No_02 "CSC号";
CM_ SG_ 2400448066 BalDchg_PosCellLow_02 "放电均衡电芯位置_(按bit)";
CM_ SG_ 2400448066 BalDchg_PosCellHigh_02 "放电均衡电芯位置_(按bit)";
CM_ SG_ 2400448067 CSC_B_No_03 "CSC号";
CM_ SG_ 2400448067 BalDchg_PosCellLow_03 "放电均衡电芯位置_(按bit)";
CM_ SG_ 2400448067 BalDchg_PosCellHigh_03 "放电均衡电芯位置_(按bit)";
CM_ SG_ 2400448068 CSC_B_No_04 "CSC号";
CM_ SG_ 2400448068 BalDchg_PosCellLow_04 "放电均衡电芯位置_(按bit)";
CM_ SG_ 2400448068 BalDchg_PosCellHigh_04 "放电均衡电芯位置_(按bit)";
CM_ SG_ 2400448069 CSC_B_No_05 "CSC号";
CM_ SG_ 2400448069 BalDchg_PosCellLow_05 "放电均衡电芯位置_(按bit)";
CM_ SG_ 2400448069 BalDchg_PosCellHigh_05 "放电均衡电芯位置_(按bit)";
CM_ SG_ 2400448070 CSC_B_No_06 "CSC号";
CM_ SG_ 2400448070 BalDchg_PosCellLow_06 "放电均衡电芯位置_(按bit)";
CM_ SG_ 2400448070 BalDchg_PosCellHigh_06 "放电均衡电芯位置_(按bit)";
CM_ SG_ 2400448071 CSC_B_No_07 "CSC号";
CM_ SG_ 2400448071 BalDchg_PosCellLow_07 "放电均衡电芯位置_(按bit)";
CM_ SG_ 2400448071 BalDchg_PosCellHigh_07 "放电均衡电芯位置_(按bit)";
CM_ SG_ 2400448072 CSC_B_No_08 "CSC号";
CM_ SG_ 2400448072 BalDchg_PosCellLow_08 "放电均衡电芯位置_(按bit)";
CM_ SG_ 2400448072 BalDchg_PosCellHigh_08 "放电均衡电芯位置_(按bit)";
CM_ SG_ 2400448073 CSC_B_No_09 "CSC号";
CM_ SG_ 2400448073 BalDchg_PosCellLow_09 "放电均衡电芯位置_(按bit)";
CM_ SG_ 2400448073 BalDchg_PosCellHigh_09 "放电均衡电芯位置_(按bit)";
CM_ SG_ 2400448074 CSC_B_No_10 "CSC号";
CM_ SG_ 2400448074 BalDchg_PosCellLow_10 "放电均衡电芯位置_(按bit)";
CM_ SG_ 2400448074 BalDchg_PosCellHigh_10 "放电均衡电芯位置_(按bit)";
CM_ SG_ 2400448075 CSC_B_No_11 "CSC号";
CM_ SG_ 2400448075 BalDchg_PosCellLow_11 "放电均衡电芯位置_(按bit)";
CM_ SG_ 2400448075 BalDchg_PosCellHigh_11 "放电均衡电芯位置_(按bit)";
CM_ SG_ 2400448076 CSC_B_No_12 "CSC号";
CM_ SG_ 2400448076 BalDchg_PosCellLow_12 "放电均衡电芯位置_(按bit)";
CM_ SG_ 2400448076 BalDchg_PosCellHigh_12 "放电均衡电芯位置_(按bit)";
CM_ SG_ 2400448077 CSC_B_No_13 "CSC号";
CM_ SG_ 2400448077 BalDchg_PosCellLow_13 "放电均衡电芯位置_(按bit)";
CM_ SG_ 2400448077 BalDchg_PosCellHigh_13 "放电均衡电芯位置_(按bit)";
CM_ SG_ 2400448078 CSC_B_No_14 "CSC号";
CM_ SG_ 2400448078 BalDchg_PosCellLow_14 "放电均衡电芯位置_(按bit)";
CM_ SG_ 2400448078 BalDchg_PosCellHigh_14 "放电均衡电芯位置_(按bit)";
CM_ SG_ 2400448079 CSC_B_No_15 "CSC号";
CM_ SG_ 2400448079 BalDchg_PosCellLow_15 "放电均衡电芯位置_(按bit)";
CM_ SG_ 2400448079 BalDchg_PosCellHigh_15 "放电均衡电芯位置_(按bit)";
CM_ SG_ 2400448080 CSC_B_No_16 "CSC号";
CM_ SG_ 2400448080 BalDchg_PosCellLow_16 "放电均衡电芯位置_(按bit)";
CM_ SG_ 2400448080 BalDchg_PosCellHigh_16 "放电均衡电芯位置_(按bit)";
CM_ SG_ 2400448081 CSC_B_No_17 "CSC号";
CM_ SG_ 2400448081 BalDchg_PosCellLow_17 "放电均衡电芯位置_(按bit)";
CM_ SG_ 2400448081 BalDchg_PosCellHigh_17 "放电均衡电芯位置_(按bit)";
CM_ SG_ 2400448082 CSC_B_No_18 "CSC号";
CM_ SG_ 2400448082 BalDchg_PosCellLow_18 "放电均衡电芯位置_(按bit)";
CM_ SG_ 2400448082 BalDchg_PosCellHigh_18 "放电均衡电芯位置_(按bit)";
CM_ SG_ 2400448083 CSC_B_No_19 "CSC号";
CM_ SG_ 2400448083 BalDchg_PosCellLow_19 "放电均衡电芯位置_(按bit)";
CM_ SG_ 2400448083 BalDchg_PosCellHigh_19 "放电均衡电芯位置_(按bit)";
CM_ SG_ 2400448084 CSC_B_No_20 "CSC号";
CM_ SG_ 2400448084 BalDchg_PosCellLow_20 "放电均衡电芯位置_(按bit)";
CM_ SG_ 2400448084 BalDchg_PosCellHigh_20 "放电均衡电芯位置_(按bit)";
CM_ SG_ 2400448085 CSC_B_No_21 "CSC号";
CM_ SG_ 2400448085 BalDchg_PosCellLow_21 "放电均衡电芯位置_(按bit)";
CM_ SG_ 2400448085 BalDchg_PosCellHigh_21 "放电均衡电芯位置_(按bit)";
CM_ SG_ 2400448086 CSC_B_No_22 "CSC号";
CM_ SG_ 2400448086 BalDchg_PosCellLow_22 "放电均衡电芯位置_(按bit)";
CM_ SG_ 2400448086 BalDchg_PosCellHigh_22 "放电均衡电芯位置_(按bit)";
CM_ SG_ 2400448087 CSC_B_No_23 "CSC号";
CM_ SG_ 2400448087 BalDchg_PosCellLow_23 "放电均衡电芯位置_(按bit)";
CM_ SG_ 2400448087 BalDchg_PosCellHigh_23 "放电均衡电芯位置_(按bit)";
CM_ SG_ 2400448088 CSC_B_No_24 "CSC号";
CM_ SG_ 2400448088 BalDchg_PosCellLow_24 "放电均衡电芯位置_(按bit)";
CM_ SG_ 2400448088 BalDchg_PosCellHigh_24 "放电均衡电芯位置_(按bit)";
CM_ SG_ 2400448089 CSC_B_No_25 "CSC号";
CM_ SG_ 2400448089 BalDchg_PosCellLow_25 "放电均衡电芯位置_(按bit)";
CM_ SG_ 2400448089 BalDchg_PosCellHigh_25 "放电均衡电芯位置_(按bit)";
CM_ SG_ 2400448090 CSC_B_No_26 "CSC号";
CM_ SG_ 2400448090 BalDchg_PosCellLow_26 "放电均衡电芯位置_(按bit)";
CM_ SG_ 2400448090 BalDchg_PosCellHigh_26 "放电均衡电芯位置_(按bit)";
CM_ SG_ 2400448091 CSC_B_No_27 "CSC号";
CM_ SG_ 2400448091 BalDchg_PosCellLow_27 "放电均衡电芯位置_(按bit)";
CM_ SG_ 2400448091 BalDchg_PosCellHigh_27 "放电均衡电芯位置_(按bit)";
CM_ SG_ 2400448092 CSC_B_No_28 "CSC号";
CM_ SG_ 2400448092 BalDchg_PosCellLow_28 "放电均衡电芯位置_(按bit)";
CM_ SG_ 2400448092 BalDchg_PosCellHigh_28 "放电均衡电芯位置_(按bit)";
CM_ SG_ 2400448093 CSC_B_No_29 "CSC号";
CM_ SG_ 2400448093 BalDchg_PosCellLow_29 "放电均衡电芯位置_(按bit)";
CM_ SG_ 2400448093 BalDchg_PosCellHigh_29 "放电均衡电芯位置_(按bit)";
CM_ SG_ 2400448094 CSC_B_No_30 "CSC号";
CM_ SG_ 2400448094 BalDchg_PosCellLow_30 "放电均衡电芯位置_(按bit)";
CM_ SG_ 2400448094 BalDchg_PosCellHigh_30 "放电均衡电芯位置_(按bit)";
CM_ SG_ 2400448095 CSC_B_No_31 "CSC号";
CM_ SG_ 2400448095 BalDchg_PosCellLow_31 "放电均衡电芯位置_(按bit)";
CM_ SG_ 2400448095 BalDchg_PosCellHigh_31 "放电均衡电芯位置_(按bit)";
CM_ SG_ 2400448096 CSC_B_No_32 "CSC号";
CM_ SG_ 2400448096 BalDchg_PosCellLow_32 "放电均衡电芯位置_(按bit)";
CM_ SG_ 2400448096 BalDchg_PosCellHigh_32 "放电均衡电芯位置_(按bit)";
CM_ SG_ 2400448097 CSC_B_No_33 "CSC号";
CM_ SG_ 2400448097 BalDchg_PosCellLow_33 "放电均衡电芯位置_(按bit)";
CM_ SG_ 2400448097 BalDchg_PosCellHigh_33 "放电均衡电芯位置_(按bit)";
CM_ SG_ 2400448098 CSC_B_No_34 "CSC号";
CM_ SG_ 2400448098 BalDchg_PosCellLow_34 "放电均衡电芯位置_(按bit)";
CM_ SG_ 2400448098 BalDchg_PosCellHigh_34 "放电均衡电芯位置_(按bit)";
CM_ SG_ 2400448099 CSC_B_No_35 "CSC号";
CM_ SG_ 2400448099 BalDchg_PosCellLow_35 "放电均衡电芯位置_(按bit)";
CM_ SG_ 2400448099 BalDchg_PosCellHigh_35 "放电均衡电芯位置_(按bit)";
CM_ SG_ 2400448100 CSC_B_No_36 "CSC号";
CM_ SG_ 2400448100 BalDchg_PosCellLow_36 "放电均衡电芯位置_(按bit)";
CM_ SG_ 2400448100 BalDchg_PosCellHigh_36 "放电均衡电芯位置_(按bit)";
CM_ SG_ 2400448101 CSC_B_No_37 "CSC号";
CM_ SG_ 2400448101 BalDchg_PosCellLow_37 "放电均衡电芯位置_(按bit)";
CM_ SG_ 2400448101 BalDchg_PosCellHigh_37 "放电均衡电芯位置_(按bit)";
CM_ SG_ 2400448102 CSC_B_No_38 "CSC号";
CM_ SG_ 2400448102 BalDchg_PosCellLow_38 "放电均衡电芯位置_(按bit)";
CM_ SG_ 2400448102 BalDchg_PosCellHigh_38 "放电均衡电芯位置_(按bit)";
CM_ SG_ 2400448103 CSC_B_No_39 "CSC号";
CM_ SG_ 2400448103 BalDchg_PosCellLow_39 "放电均衡电芯位置_(按bit)";
CM_ SG_ 2400448103 BalDchg_PosCellHigh_39 "放电均衡电芯位置_(按bit)";
CM_ SG_ 2400448104 CSC_B_No_40 "CSC号";
CM_ SG_ 2400448104 BalDchg_PosCellLow_40 "放电均衡电芯位置_(按bit)";
CM_ SG_ 2400448104 BalDchg_PosCellHigh_40 "放电均衡电芯位置_(按bit)";
CM_ SG_ 2400448105 CSC_B_No_41 "CSC号";
CM_ SG_ 2400448105 BalDchg_PosCellLow_41 "放电均衡电芯位置_(按bit)";
CM_ SG_ 2400448105 BalDchg_PosCellHigh_41 "放电均衡电芯位置_(按bit)";
CM_ SG_ 2400448106 CSC_B_No_42 "CSC号";
CM_ SG_ 2400448106 BalDchg_PosCellLow_42 "放电均衡电芯位置_(按bit)";
CM_ SG_ 2400448106 BalDchg_PosCellHigh_42 "放电均衡电芯位置_(按bit)";
CM_ SG_ 2400448107 CSC_B_No_43 "CSC号";
CM_ SG_ 2400448107 BalDchg_PosCellLow_43 "放电均衡电芯位置_(按bit)";
CM_ SG_ 2400448107 BalDchg_PosCellHigh_43 "放电均衡电芯位置_(按bit)";
CM_ SG_ 2400448108 CSC_B_No_44 "CSC号";
CM_ SG_ 2400448108 BalDchg_PosCellLow_44 "放电均衡电芯位置_(按bit)";
CM_ SG_ 2400448108 BalDchg_PosCellHigh_44 "放电均衡电芯位置_(按bit)";
CM_ SG_ 2400448109 CSC_B_No_45 "CSC号";
CM_ SG_ 2400448109 BalDchg_PosCellLow_45 "放电均衡电芯位置_(按bit)";
CM_ SG_ 2400448109 BalDchg_PosCellHigh_45 "放电均衡电芯位置_(按bit)";
CM_ SG_ 2400448110 CSC_B_No_46 "CSC号";
CM_ SG_ 2400448110 BalDchg_PosCellLow_46 "放电均衡电芯位置_(按bit)";
CM_ SG_ 2400448110 BalDchg_PosCellHigh_46 "放电均衡电芯位置_(按bit)";
CM_ SG_ 2400448111 CSC_B_No_47 "CSC号";
CM_ SG_ 2400448111 BalDchg_PosCellLow_47 "放电均衡电芯位置_(按bit)";
CM_ SG_ 2400448111 BalDchg_PosCellHigh_47 "放电均衡电芯位置_(按bit)";
CM_ SG_ 2400448112 CSC_B_No_48 "CSC号";
CM_ SG_ 2400448112 BalDchg_PosCellLow_48 "放电均衡电芯位置_(按bit)";
CM_ SG_ 2400448112 BalDchg_PosCellHigh_48 "放电均衡电芯位置_(按bit)";
CM_ SG_ 2400448113 CSC_B_No_49 "CSC号";
CM_ SG_ 2400448113 BalDchg_PosCellLow_49 "放电均衡电芯位置_(按bit)";
CM_ SG_ 2400448113 BalDchg_PosCellHigh_49 "放电均衡电芯位置_(按bit)";
CM_ SG_ 2400448114 CSC_B_No_50 "CSC号";
CM_ SG_ 2400448114 BalDchg_PosCellLow_50 "放电均衡电芯位置_(按bit)";
CM_ SG_ 2400448114 BalDchg_PosCellHigh_50 "放电均衡电芯位置_(按bit)";
CM_ SG_ 2400448115 CSC_B_No_51 "CSC号";
CM_ SG_ 2400448115 BalDchg_PosCellLow_51 "放电均衡电芯位置_(按bit)";
CM_ SG_ 2400448115 BalDchg_PosCellHigh_51 "放电均衡电芯位置_(按bit)";
CM_ SG_ 2400448116 CSC_B_No_52 "CSC号";
CM_ SG_ 2400448116 BalDchg_PosCellLow_52 "放电均衡电芯位置_(按bit)";
CM_ SG_ 2400448116 BalDchg_PosCellHigh_52 "放电均衡电芯位置_(按bit)";
CM_ SG_ 2400448117 CSC_B_No_53 "CSC号";
CM_ SG_ 2400448117 BalDchg_PosCellLow_53 "放电均衡电芯位置_(按bit)";
CM_ SG_ 2400448117 BalDchg_PosCellHigh_53 "放电均衡电芯位置_(按bit)";
CM_ SG_ 2400448118 CSC_B_No_54 "CSC号";
CM_ SG_ 2400448118 BalDchg_PosCellLow_54 "放电均衡电芯位置_(按bit)";
CM_ SG_ 2400448118 BalDchg_PosCellHigh_54 "放电均衡电芯位置_(按bit)";
CM_ SG_ 2400448119 CSC_B_No_55 "CSC号";
CM_ SG_ 2400448119 BalDchg_PosCellLow_55 "放电均衡电芯位置_(按bit)";
CM_ SG_ 2400448119 BalDchg_PosCellHigh_55 "放电均衡电芯位置_(按bit)";
CM_ SG_ 2400448120 CSC_B_No_56 "CSC号";
CM_ SG_ 2400448120 BalDchg_PosCellLow_56 "放电均衡电芯位置_(按bit)";
CM_ SG_ 2400448120 BalDchg_PosCellHigh_56 "放电均衡电芯位置_(按bit)";
CM_ SG_ 2400448121 CSC_B_No_57 "CSC号";
CM_ SG_ 2400448121 BalDchg_PosCellLow_57 "放电均衡电芯位置_(按bit)";
CM_ SG_ 2400448121 BalDchg_PosCellHigh_57 "放电均衡电芯位置_(按bit)";
CM_ SG_ 2400448122 CSC_B_No_58 "CSC号";
CM_ SG_ 2400448122 BalDchg_PosCellLow_58 "放电均衡电芯位置_(按bit)";
CM_ SG_ 2400448122 BalDchg_PosCellHigh_58 "放电均衡电芯位置_(按bit)";
CM_ SG_ 2400448123 CSC_B_No_59 "CSC号";
CM_ SG_ 2400448123 BalDchg_PosCellLow_59 "放电均衡电芯位置_(按bit)";
CM_ SG_ 2400448123 BalDchg_PosCellHigh_59 "放电均衡电芯位置_(按bit)";
CM_ SG_ 2400448124 CSC_B_No_60 "CSC号";
CM_ SG_ 2400448124 BalDchg_PosCellLow_60 "放电均衡电芯位置_(按bit)";
CM_ SG_ 2400448124 BalDchg_PosCellHigh_60 "放电均衡电芯位置_(按bit)";
CM_ SG_ 2400448125 CSC_B_No_61 "CSC号";
CM_ SG_ 2400448125 BalDchg_PosCellLow_61 "放电均衡电芯位置_(按bit)";
CM_ SG_ 2400448125 BalDchg_PosCellHigh_61 "放电均衡电芯位置_(按bit)";
CM_ SG_ 2400448126 CSC_B_No_62 "CSC号";
CM_ SG_ 2400448126 BalDchg_PosCellLow_62 "放电均衡电芯位置_(按bit)";
CM_ SG_ 2400448126 BalDchg_PosCellHigh_62 "放电均衡电芯位置_(按bit)";
CM_ SG_ 2400448127 CSC_B_No_63 "CSC号";
CM_ SG_ 2400448127 BalDchg_PosCellLow_63 "放电均衡电芯位置_(按bit)";
CM_ SG_ 2400448127 BalDchg_PosCellHigh_63 "放电均衡电芯位置_(按bit)";
CM_ SG_ 2400579137 CSC_B_S_No_01 "CSC号";
CM_ SG_ 2400579137 State_Balance_Status_01 "均衡状态";
CM_ SG_ 2400579137 State_Balance_Fault_01 "均衡关闭故障";
CM_ SG_ 2400579138 CSC_B_S_No_02 "CSC号";
CM_ SG_ 2400579138 State_Balance_Status_02 "均衡状态";
CM_ SG_ 2400579138 State_Balance_Fault_02 "均衡关闭故障";
CM_ SG_ 2400579139 CSC_B_S_No_03 "CSC号";
CM_ SG_ 2400579139 State_Balance_Status_03 "均衡状态";
CM_ SG_ 2400579139 State_Balance_Fault_03 "均衡关闭故障";
CM_ SG_ 2400579140 CSC_B_S_No_04 "CSC号";
CM_ SG_ 2400579140 State_Balance_Status_04 "均衡状态";
CM_ SG_ 2400579140 State_Balance_Fault_04 "均衡关闭故障";
CM_ SG_ 2400579141 CSC_B_S_No_05 "CSC号";
CM_ SG_ 2400579141 State_Balance_Status_05 "均衡状态";
CM_ SG_ 2400579141 State_Balance_Fault_05 "均衡关闭故障";
CM_ SG_ 2400579142 CSC_B_S_No_06 "CSC号";
CM_ SG_ 2400579142 State_Balance_Status_06 "均衡状态";
CM_ SG_ 2400579142 State_Balance_Fault_06 "均衡关闭故障";
CM_ SG_ 2400579143 CSC_B_S_No_07 "CSC号";
CM_ SG_ 2400579143 State_Balance_Status_07 "均衡状态";
CM_ SG_ 2400579143 State_Balance_Fault_07 "均衡关闭故障";
CM_ SG_ 2400579144 CSC_B_S_No_08 "CSC号";
CM_ SG_ 2400579144 State_Balance_Status_08 "均衡状态";
CM_ SG_ 2400579144 State_Balance_Fault_08 "均衡关闭故障";
CM_ SG_ 2400579145 CSC_B_S_No_09 "CSC号";
CM_ SG_ 2400579145 State_Balance_Status_09 "均衡状态";
CM_ SG_ 2400579145 State_Balance_Fault_09 "均衡关闭故障";
CM_ SG_ 2400579146 CSC_B_S_No_10 "CSC号";
CM_ SG_ 2400579146 State_Balance_Status_10 "均衡状态";
CM_ SG_ 2400579146 State_Balance_Fault_10 "均衡关闭故障";
CM_ SG_ 2400579147 CSC_B_S_No_11 "CSC号";
CM_ SG_ 2400579147 State_Balance_Status_11 "均衡状态";
CM_ SG_ 2400579147 State_Balance_Fault_11 "均衡关闭故障";
CM_ SG_ 2400579148 CSC_B_S_No_12 "CSC号";
CM_ SG_ 2400579148 State_Balance_Status_12 "均衡状态";
CM_ SG_ 2400579148 State_Balance_Fault_12 "均衡关闭故障";
CM_ SG_ 2400579149 CSC_B_S_No_13 "CSC号";
CM_ SG_ 2400579149 State_Balance_Status_13 "均衡状态";
CM_ SG_ 2400579149 State_Balance_Fault_13 "均衡关闭故障";
CM_ SG_ 2400579150 CSC_B_S_No_14 "CSC号";
CM_ SG_ 2400579150 State_Balance_Status_14 "均衡状态";
CM_ SG_ 2400579150 State_Balance_Fault_14 "均衡关闭故障";
CM_ SG_ 2400579151 CSC_B_S_No_15 "CSC号";
CM_ SG_ 2400579151 State_Balance_Status_15 "均衡状态";
CM_ SG_ 2400579151 State_Balance_Fault_15 "均衡关闭故障";
CM_ SG_ 2400579152 CSC_B_S_No_16 "CSC号";
CM_ SG_ 2400579152 State_Balance_Status_16 "均衡状态";
CM_ SG_ 2400579152 State_Balance_Fault_16 "均衡关闭故障";
CM_ SG_ 2400579153 CSC_B_S_No_17 "CSC号";
CM_ SG_ 2400579153 State_Balance_Status_17 "均衡状态";
CM_ SG_ 2400579153 State_Balance_Fault_17 "均衡关闭故障";
CM_ SG_ 2400579154 CSC_B_S_No_18 "CSC号";
CM_ SG_ 2400579154 State_Balance_Status_18 "均衡状态";
CM_ SG_ 2400579154 State_Balance_Fault_18 "均衡关闭故障";
CM_ SG_ 2400579155 CSC_B_S_No_19 "CSC号";
CM_ SG_ 2400579155 State_Balance_Status_19 "均衡状态";
CM_ SG_ 2400579155 State_Balance_Fault_19 "均衡关闭故障";
CM_ SG_ 2400579156 CSC_B_S_No_20 "CSC号";
CM_ SG_ 2400579156 State_Balance_Status_20 "均衡状态";
CM_ SG_ 2400579156 State_Balance_Fault_20 "均衡关闭故障";
CM_ SG_ 2400579157 CSC_B_S_No_21 "CSC号";
CM_ SG_ 2400579157 State_Balance_Status_21 "均衡状态";
CM_ SG_ 2400579157 State_Balance_Fault_21 "均衡关闭故障";
CM_ SG_ 2400579158 CSC_B_S_No_22 "CSC号";
CM_ SG_ 2400579158 State_Balance_Status_22 "均衡状态";
CM_ SG_ 2400579158 State_Balance_Fault_22 "均衡关闭故障";
CM_ SG_ 2400579159 CSC_B_S_No_23 "CSC号";
CM_ SG_ 2400579159 State_Balance_Status_23 "均衡状态";
CM_ SG_ 2400579159 State_Balance_Fault_23 "均衡关闭故障";
CM_ SG_ 2400579160 CSC_B_S_No_24 "CSC号";
CM_ SG_ 2400579160 State_Balance_Status_24 "均衡状态";
CM_ SG_ 2400579160 State_Balance_Fault_24 "均衡关闭故障";
CM_ SG_ 2400579161 CSC_B_S_No_25 "CSC号";
CM_ SG_ 2400579161 State_Balance_Status_25 "均衡状态";
CM_ SG_ 2400579161 State_Balance_Fault_25 "均衡关闭故障";
CM_ SG_ 2400579162 CSC_B_S_No_26 "CSC号";
CM_ SG_ 2400579162 State_Balance_Status_26 "均衡状态";
CM_ SG_ 2400579162 State_Balance_Fault_26 "均衡关闭故障";
CM_ SG_ 2400579163 CSC_B_S_No_27 "CSC号";
CM_ SG_ 2400579163 State_Balance_Status_27 "均衡状态";
CM_ SG_ 2400579163 State_Balance_Fault_27 "均衡关闭故障";
CM_ SG_ 2400579164 CSC_B_S_No_28 "CSC号";
CM_ SG_ 2400579164 State_Balance_Status_28 "均衡状态";
CM_ SG_ 2400579164 State_Balance_Fault_28 "均衡关闭故障";
CM_ SG_ 2400579165 CSC_B_S_No_29 "CSC号";
CM_ SG_ 2400579165 State_Balance_Status_29 "均衡状态";
CM_ SG_ 2400579165 State_Balance_Fault_29 "均衡关闭故障";
CM_ SG_ 2400579166 CSC_B_S_No_30 "CSC号";
CM_ SG_ 2400579166 State_Balance_Status_30 "均衡状态";
CM_ SG_ 2400579166 State_Balance_Fault_30 "均衡关闭故障";
CM_ SG_ 2400579167 CSC_B_S_No_31 "CSC号";
CM_ SG_ 2400579167 State_Balance_Status_31 "均衡状态";
CM_ SG_ 2400579167 State_Balance_Fault_31 "均衡关闭故障";
CM_ SG_ 2400579168 CSC_B_S_No_32 "CSC号";
CM_ SG_ 2400579168 State_Balance_Status_32 "均衡状态";
CM_ SG_ 2400579168 State_Balance_Fault_32 "均衡关闭故障";
CM_ SG_ 2400579169 CSC_B_S_No_33 "CSC号";
CM_ SG_ 2400579169 State_Balance_Status_33 "均衡状态";
CM_ SG_ 2400579169 State_Balance_Fault_33 "均衡关闭故障";
CM_ SG_ 2400579170 CSC_B_S_No_34 "CSC号";
CM_ SG_ 2400579170 State_Balance_Status_34 "均衡状态";
CM_ SG_ 2400579170 State_Balance_Fault_34 "均衡关闭故障";
CM_ SG_ 2400579171 CSC_B_S_No_35 "CSC号";
CM_ SG_ 2400579171 State_Balance_Status_35 "均衡状态";
CM_ SG_ 2400579171 State_Balance_Fault_35 "均衡关闭故障";
CM_ SG_ 2400579172 CSC_B_S_No_36 "CSC号";
CM_ SG_ 2400579172 State_Balance_Status_36 "均衡状态";
CM_ SG_ 2400579172 State_Balance_Fault_36 "均衡关闭故障";
CM_ SG_ 2400579173 CSC_B_S_No_37 "CSC号";
CM_ SG_ 2400579173 State_Balance_Status_37 "均衡状态";
CM_ SG_ 2400579173 State_Balance_Fault_37 "均衡关闭故障";
CM_ SG_ 2400579174 CSC_B_S_No_38 "CSC号";
CM_ SG_ 2400579174 State_Balance_Status_38 "均衡状态";
CM_ SG_ 2400579174 State_Balance_Fault_38 "均衡关闭故障";
CM_ SG_ 2400579175 CSC_B_S_No_39 "CSC号";
CM_ SG_ 2400579175 State_Balance_Status_39 "均衡状态";
CM_ SG_ 2400579175 State_Balance_Fault_39 "均衡关闭故障";
CM_ SG_ 2400579176 CSC_B_S_No_40 "CSC号";
CM_ SG_ 2400579176 State_Balance_Status_40 "均衡状态";
CM_ SG_ 2400579176 State_Balance_Fault_40 "均衡关闭故障";
CM_ SG_ 2400579177 CSC_B_S_No_41 "CSC号";
CM_ SG_ 2400579177 State_Balance_Status_41 "均衡状态";
CM_ SG_ 2400579177 State_Balance_Fault_41 "均衡关闭故障";
CM_ SG_ 2400579178 CSC_B_S_No_42 "CSC号";
CM_ SG_ 2400579178 State_Balance_Status_42 "均衡状态";
CM_ SG_ 2400579178 State_Balance_Fault_42 "均衡关闭故障";
CM_ SG_ 2400579179 CSC_B_S_No_43 "CSC号";
CM_ SG_ 2400579179 State_Balance_Status_43 "均衡状态";
CM_ SG_ 2400579179 State_Balance_Fault_43 "均衡关闭故障";
CM_ SG_ 2400579180 CSC_B_S_No_44 "CSC号";
CM_ SG_ 2400579180 State_Balance_Status_44 "均衡状态";
CM_ SG_ 2400579180 State_Balance_Fault_44 "均衡关闭故障";
CM_ SG_ 2400579181 CSC_B_S_No_45 "CSC号";
CM_ SG_ 2400579181 State_Balance_Status_45 "均衡状态";
CM_ SG_ 2400579181 State_Balance_Fault_45 "均衡关闭故障";
CM_ SG_ 2400579182 CSC_B_S_No_46 "CSC号";
CM_ SG_ 2400579182 State_Balance_Status_46 "均衡状态";
CM_ SG_ 2400579182 State_Balance_Fault_46 "均衡关闭故障";
CM_ SG_ 2400579183 CSC_B_S_No_47 "CSC号";
CM_ SG_ 2400579183 State_Balance_Status_47 "均衡状态";
CM_ SG_ 2400579183 State_Balance_Fault_47 "均衡关闭故障";
CM_ SG_ 2400579184 CSC_B_S_No_48 "CSC号";
CM_ SG_ 2400579184 State_Balance_Status_48 "均衡状态";
CM_ SG_ 2400579184 State_Balance_Fault_48 "均衡关闭故障";
CM_ SG_ 2400579185 CSC_B_S_No_49 "CSC号";
CM_ SG_ 2400579185 State_Balance_Status_49 "均衡状态";
CM_ SG_ 2400579185 State_Balance_Fault_49 "均衡关闭故障";
CM_ SG_ 2400579186 CSC_B_S_No_50 "CSC号";
CM_ SG_ 2400579186 State_Balance_Status_50 "均衡状态";
CM_ SG_ 2400579186 State_Balance_Fault_50 "均衡关闭故障";
CM_ SG_ 2400579187 CSC_B_S_No_51 "CSC号";
CM_ SG_ 2400579187 State_Balance_Status_51 "均衡状态";
CM_ SG_ 2400579187 State_Balance_Fault_51 "均衡关闭故障";
CM_ SG_ 2400579188 CSC_B_S_No_52 "CSC号";
CM_ SG_ 2400579188 State_Balance_Status_52 "均衡状态";
CM_ SG_ 2400579188 State_Balance_Fault_52 "均衡关闭故障";
CM_ SG_ 2400579189 CSC_B_S_No_53 "CSC号";
CM_ SG_ 2400579189 State_Balance_Status_53 "均衡状态";
CM_ SG_ 2400579189 State_Balance_Fault_53 "均衡关闭故障";
CM_ SG_ 2400579190 CSC_B_S_No_54 "CSC号";
CM_ SG_ 2400579190 State_Balance_Status_54 "均衡状态";
CM_ SG_ 2400579190 State_Balance_Fault_54 "均衡关闭故障";
CM_ SG_ 2400579191 CSC_B_S_No_55 "CSC号";
CM_ SG_ 2400579191 State_Balance_Status_55 "均衡状态";
CM_ SG_ 2400579191 State_Balance_Fault_55 "均衡关闭故障";
CM_ SG_ 2400579192 CSC_B_S_No_56 "CSC号";
CM_ SG_ 2400579192 State_Balance_Status_56 "均衡状态";
CM_ SG_ 2400579192 State_Balance_Fault_56 "均衡关闭故障";
VAL_ 2400382583 CSC_T_No_55 1 "CSC 1" 2 "CSC 2" 3 "CSC 3" 4 "CSC 4" 5 "CSC 5" 6 "CSC 6" ;
VAL_ 2400382583 CSC_Tcell_01_55 255 "Invalid" ;
VAL_ 2400382583 CSC_Tcell_02_55 255 "Invalid" ;
VAL_ 2400382583 CSC_Tcell_03_55 255 "Invalid" ;
VAL_ 2400382583 CSC_Tcell_04_55 255 "Invalid" ;
VAL_ 2400382583 CSC_Tcell_05_55 255 "Invalid" ;
VAL_ 2400382583 CSC_Tcell_06_55 255 "Invalid" ;
VAL_ 2400382583 CSC_Tcell_07_55 255 "Invalid" ;
VAL_ 2400382583 CSC_Tcell_08_55 255 "Invalid" ;
VAL_ 2400382583 CSC_Tcell_09_55 255 "Invalid" ;
VAL_ 2400382583 CSC_Tcell_10_55 255 "Invalid" ;
VAL_ 2400382583 CSC_Tcell_11_55 255 "Invalid" ;
VAL_ 2400382583 CSC_Tcell_12_55 255 "Invalid" ;
VAL_ 2400382583 CSC_Tcell_13_55 255 "Invalid" ;
VAL_ 2400382583 CSC_Tcell_14_55 255 "Invalid" ;
VAL_ 2400382583 CSC_Tcell_15_55 255 "Invalid" ;
VAL_ 2400382583 CSC_Tcell_16_55 255 "Invalid" ;
VAL_ 2400382583 CSC_Tcell_17_55 255 "Invalid" ;
VAL_ 2400382583 CSC_Tcell_18_55 255 "Invalid" ;
VAL_ 2400382583 CSC_Tcell_19_55 255 "Invalid" ;
VAL_ 2400382583 CSC_Tcell_20_55 255 "Invalid" ;
VAL_ 2400382583 CSC_Tcell_21_55 255 "Invalid" ;
VAL_ 2400382583 CSC_Tcell_22_55 255 "Invalid" ;
VAL_ 2400382583 CSC_Tcell_23_55 255 "Invalid" ;
VAL_ 2400382583 CSC_Tcell_24_55 255 "Invalid" ;
VAL_ 2400382583 CSC_Tcell_25_55 255 "Invalid" ;
VAL_ 2400382583 CSC_Tcell_26_55 255 "Invalid" ;
VAL_ 2400382583 CSC_Tcell_27_55 255 "Invalid" ;
VAL_ 2400382583 CSC_Tcell_28_55 255 "Invalid" ;
VAL_ 2400382583 CSC_Tcell_29_55 255 "Invalid" ;
VAL_ 2400382583 CSC_Tcell_30_55 255 "Invalid" ;
VAL_ 2400382583 CSC_Tcell_31_55 255 "Invalid" ;
VAL_ 2400382583 CSC_Tcell_32_55 255 "Invalid" ;
VAL_ 2400382583 CSC_Tcell_33_55 255 "Invalid" ;
VAL_ 2400382583 CSC_Tcell_34_55 255 "Invalid" ;
VAL_ 2400382583 CSC_Tcell_35_55 255 "Invalid" ;
VAL_ 2400382583 CSC_Tcell_36_55 255 "Invalid" ;
VAL_ 2400382583 CSC_Tcell_37_55 255 "Invalid" ;
VAL_ 2400382583 CSC_Tcell_38_55 255 "Invalid" ;
VAL_ 2400382583 CSC_Tcell_39_55 255 "Invalid" ;
VAL_ 2400382583 CSC_Tcell_40_55 255 "Invalid" ;
VAL_ 2400382583 CSC_Tcell_41_55 255 "Invalid" ;
VAL_ 2400382583 CSC_Tcell_42_55 255 "Invalid" ;
VAL_ 2400382583 CSC_Tcell_43_55 255 "Invalid" ;
VAL_ 2400382583 CSC_Tcell_44_55 255 "Invalid" ;
VAL_ 2400382583 CSC_Tcell_45_55 255 "Invalid" ;
VAL_ 2400382583 CSC_Tcell_46_55 255 "Invalid" ;
VAL_ 2400382583 CSC_Tcell_47_55 255 "Invalid" ;
VAL_ 2400382583 CSC_Tcell_48_55 255 "Invalid" ;
VAL_ 2400382583 CSC_Tcell_49_55 255 "Invalid" ;
VAL_ 2400382583 CSC_Tcell_50_55 255 "Invalid" ;
VAL_ 2400382583 CSC_Tcell_51_55 255 "Invalid" ;
VAL_ 2400382583 CSC_Tcell_52_55 255 "Invalid" ;
VAL_ 2400382583 CSC_Tcell_53_55 255 "Invalid" ;
VAL_ 2400382583 CSC_Tcell_54_55 255 "Invalid" ;
VAL_ 2400382583 CSC_Tcell_55_55 255 "Invalid" ;
VAL_ 2400382583 CSC_Tcell_56_55 255 "Invalid" ;
VAL_ 2400382583 CSC_Tcell_57_55 255 "Invalid" ;
VAL_ 2400382583 CSC_Tcell_58_55 255 "Invalid" ;
VAL_ 2400382583 CSC_Tcell_59_55 255 "Invalid" ;
VAL_ 2400382583 CSC_Tcell_60_55 255 "Invalid" ;
VAL_ 2400382583 CSC_Tcell_61_55 255 "Invalid" ;
VAL_ 2400382583 CSC_Tcell_62_55 255 "Invalid" ;
VAL_ 2400382583 CSC_Tcell_63_55 255 "Invalid" ;
VAL_ 2400382583 CSC_Tcell_64_55 255 "Invalid" ;
VAL_ 2400382583 CSC_Tcell_65_55 255 "Invalid" ;
VAL_ 2400382583 CSC_Tcell_66_55 255 "Invalid" ;
VAL_ 2400382583 CSC_Tcell_67_55 255 "Invalid" ;
VAL_ 2400382583 CSC_Tcell_68_55 255 "Invalid" ;
VAL_ 2400382583 CSC_Tcell_69_55 255 "Invalid" ;
VAL_ 2400382583 CSC_Tcell_70_55 255 "Invalid" ;
VAL_ 2400382583 CSC_Tcell_71_55 255 "Invalid" ;
VAL_ 2400382583 CSC_Tcell_72_55 255 "Invalid" ;
VAL_ 2400382584 CSC_T_No_56 1 "CSC 1" 2 "CSC 2" 3 "CSC 3" 4 "CSC 4" 5 "CSC 5" 6 "CSC 6" ;
VAL_ 2400382584 CSC_Tcell_01_56 255 "Invalid" ;
VAL_ 2400382584 CSC_Tcell_02_56 255 "Invalid" ;
VAL_ 2400382584 CSC_Tcell_03_56 255 "Invalid" ;
VAL_ 2400382584 CSC_Tcell_04_56 255 "Invalid" ;
VAL_ 2400382584 CSC_Tcell_05_56 255 "Invalid" ;
VAL_ 2400382584 CSC_Tcell_06_56 255 "Invalid" ;
VAL_ 2400382584 CSC_Tcell_07_56 255 "Invalid" ;
VAL_ 2400382584 CSC_Tcell_08_56 255 "Invalid" ;
VAL_ 2400382584 CSC_Tcell_09_56 255 "Invalid" ;
VAL_ 2400382584 CSC_Tcell_10_56 255 "Invalid" ;
VAL_ 2400382584 CSC_Tcell_11_56 255 "Invalid" ;
VAL_ 2400382584 CSC_Tcell_12_56 255 "Invalid" ;
VAL_ 2400382584 CSC_Tcell_13_56 255 "Invalid" ;
VAL_ 2400382584 CSC_Tcell_14_56 255 "Invalid" ;
VAL_ 2400382584 CSC_Tcell_15_56 255 "Invalid" ;
VAL_ 2400382584 CSC_Tcell_16_56 255 "Invalid" ;
VAL_ 2400382584 CSC_Tcell_17_56 255 "Invalid" ;
VAL_ 2400382584 CSC_Tcell_18_56 255 "Invalid" ;
VAL_ 2400382584 CSC_Tcell_19_56 255 "Invalid" ;
VAL_ 2400382584 CSC_Tcell_20_56 255 "Invalid" ;
VAL_ 2400382584 CSC_Tcell_21_56 255 "Invalid" ;
VAL_ 2400382584 CSC_Tcell_22_56 255 "Invalid" ;
VAL_ 2400382584 CSC_Tcell_23_56 255 "Invalid" ;
VAL_ 2400382584 CSC_Tcell_24_56 255 "Invalid" ;
VAL_ 2400382584 CSC_Tcell_25_56 255 "Invalid" ;
VAL_ 2400382584 CSC_Tcell_26_56 255 "Invalid" ;
VAL_ 2400382584 CSC_Tcell_27_56 255 "Invalid" ;
VAL_ 2400382584 CSC_Tcell_28_56 255 "Invalid" ;
VAL_ 2400382584 CSC_Tcell_29_56 255 "Invalid" ;
VAL_ 2400382584 CSC_Tcell_30_56 255 "Invalid" ;
VAL_ 2400382584 CSC_Tcell_31_56 255 "Invalid" ;
VAL_ 2400382584 CSC_Tcell_32_56 255 "Invalid" ;
VAL_ 2400382584 CSC_Tcell_33_56 255 "Invalid" ;
VAL_ 2400382584 CSC_Tcell_34_56 255 "Invalid" ;
VAL_ 2400382584 CSC_Tcell_35_56 255 "Invalid" ;
VAL_ 2400382584 CSC_Tcell_36_56 255 "Invalid" ;
VAL_ 2400382584 CSC_Tcell_37_56 255 "Invalid" ;
VAL_ 2400382584 CSC_Tcell_38_56 255 "Invalid" ;
VAL_ 2400382584 CSC_Tcell_39_56 255 "Invalid" ;
VAL_ 2400382584 CSC_Tcell_40_56 255 "Invalid" ;
VAL_ 2400382584 CSC_Tcell_41_56 255 "Invalid" ;
VAL_ 2400382584 CSC_Tcell_42_56 255 "Invalid" ;
VAL_ 2400382584 CSC_Tcell_43_56 255 "Invalid" ;
VAL_ 2400382584 CSC_Tcell_44_56 255 "Invalid" ;
VAL_ 2400382584 CSC_Tcell_45_56 255 "Invalid" ;
VAL_ 2400382584 CSC_Tcell_46_56 255 "Invalid" ;
VAL_ 2400382584 CSC_Tcell_47_56 255 "Invalid" ;
VAL_ 2400382584 CSC_Tcell_48_56 255 "Invalid" ;
VAL_ 2400382584 CSC_Tcell_49_56 255 "Invalid" ;
VAL_ 2400382584 CSC_Tcell_50_56 255 "Invalid" ;
VAL_ 2400382584 CSC_Tcell_51_56 255 "Invalid" ;
VAL_ 2400382584 CSC_Tcell_52_56 255 "Invalid" ;
VAL_ 2400382584 CSC_Tcell_53_56 255 "Invalid" ;
VAL_ 2400382584 CSC_Tcell_54_56 255 "Invalid" ;
VAL_ 2400382584 CSC_Tcell_55_56 255 "Invalid" ;
VAL_ 2400382584 CSC_Tcell_56_56 255 "Invalid" ;
VAL_ 2400382584 CSC_Tcell_57_56 255 "Invalid" ;
VAL_ 2400382584 CSC_Tcell_58_56 255 "Invalid" ;
VAL_ 2400382584 CSC_Tcell_59_56 255 "Invalid" ;
VAL_ 2400382584 CSC_Tcell_60_56 255 "Invalid" ;
VAL_ 2400382584 CSC_Tcell_61_56 255 "Invalid" ;
VAL_ 2400382584 CSC_Tcell_62_56 255 "Invalid" ;
VAL_ 2400382584 CSC_Tcell_63_56 255 "Invalid" ;
VAL_ 2400382584 CSC_Tcell_64_56 255 "Invalid" ;
VAL_ 2400382584 CSC_Tcell_65_56 255 "Invalid" ;
VAL_ 2400382584 CSC_Tcell_66_56 255 "Invalid" ;
VAL_ 2400382584 CSC_Tcell_67_56 255 "Invalid" ;
VAL_ 2400382584 CSC_Tcell_68_56 255 "Invalid" ;
VAL_ 2400382584 CSC_Tcell_69_56 255 "Invalid" ;
VAL_ 2400382584 CSC_Tcell_70_56 255 "Invalid" ;
VAL_ 2400382584 CSC_Tcell_71_56 255 "Invalid" ;
VAL_ 2400382584 CSC_Tcell_72_56 255 "Invalid" ;
VAL_ 2400382585 CSC_T_No_57 1 "CSC 1" 2 "CSC 2" 3 "CSC 3" 4 "CSC 4" 5 "CSC 5" 6 "CSC 6" ;
VAL_ 2400382585 CSC_Tcell_01_57 255 "Invalid" ;
VAL_ 2400382585 CSC_Tcell_02_57 255 "Invalid" ;
VAL_ 2400382585 CSC_Tcell_03_57 255 "Invalid" ;
VAL_ 2400382585 CSC_Tcell_04_57 255 "Invalid" ;
VAL_ 2400382585 CSC_Tcell_05_57 255 "Invalid" ;
VAL_ 2400382585 CSC_Tcell_06_57 255 "Invalid" ;
VAL_ 2400382585 CSC_Tcell_07_57 255 "Invalid" ;
VAL_ 2400382585 CSC_Tcell_08_57 255 "Invalid" ;
VAL_ 2400382585 CSC_Tcell_09_57 255 "Invalid" ;
VAL_ 2400382585 CSC_Tcell_10_57 255 "Invalid" ;
VAL_ 2400382585 CSC_Tcell_11_57 255 "Invalid" ;
VAL_ 2400382585 CSC_Tcell_12_57 255 "Invalid" ;
VAL_ 2400382585 CSC_Tcell_13_57 255 "Invalid" ;
VAL_ 2400382585 CSC_Tcell_14_57 255 "Invalid" ;
VAL_ 2400382585 CSC_Tcell_15_57 255 "Invalid" ;
VAL_ 2400382585 CSC_Tcell_16_57 255 "Invalid" ;
VAL_ 2400382585 CSC_Tcell_17_57 255 "Invalid" ;
VAL_ 2400382585 CSC_Tcell_18_57 255 "Invalid" ;
VAL_ 2400382585 CSC_Tcell_19_57 255 "Invalid" ;
VAL_ 2400382585 CSC_Tcell_20_57 255 "Invalid" ;
VAL_ 2400382585 CSC_Tcell_21_57 255 "Invalid" ;
VAL_ 2400382585 CSC_Tcell_22_57 255 "Invalid" ;
VAL_ 2400382585 CSC_Tcell_23_57 255 "Invalid" ;
VAL_ 2400382585 CSC_Tcell_24_57 255 "Invalid" ;
VAL_ 2400382585 CSC_Tcell_25_57 255 "Invalid" ;
VAL_ 2400382585 CSC_Tcell_26_57 255 "Invalid" ;
VAL_ 2400382585 CSC_Tcell_27_57 255 "Invalid" ;
VAL_ 2400382585 CSC_Tcell_28_57 255 "Invalid" ;
VAL_ 2400382585 CSC_Tcell_29_57 255 "Invalid" ;
VAL_ 2400382585 CSC_Tcell_30_57 255 "Invalid" ;
VAL_ 2400382585 CSC_Tcell_31_57 255 "Invalid" ;
VAL_ 2400382585 CSC_Tcell_32_57 255 "Invalid" ;
VAL_ 2400382585 CSC_Tcell_33_57 255 "Invalid" ;
VAL_ 2400382585 CSC_Tcell_34_57 255 "Invalid" ;
VAL_ 2400382585 CSC_Tcell_35_57 255 "Invalid" ;
VAL_ 2400382585 CSC_Tcell_36_57 255 "Invalid" ;
VAL_ 2400382585 CSC_Tcell_37_57 255 "Invalid" ;
VAL_ 2400382585 CSC_Tcell_38_57 255 "Invalid" ;
VAL_ 2400382585 CSC_Tcell_39_57 255 "Invalid" ;
VAL_ 2400382585 CSC_Tcell_40_57 255 "Invalid" ;
VAL_ 2400382585 CSC_Tcell_41_57 255 "Invalid" ;
VAL_ 2400382585 CSC_Tcell_42_57 255 "Invalid" ;
VAL_ 2400382585 CSC_Tcell_43_57 255 "Invalid" ;
VAL_ 2400382585 CSC_Tcell_44_57 255 "Invalid" ;
VAL_ 2400382585 CSC_Tcell_45_57 255 "Invalid" ;
VAL_ 2400382585 CSC_Tcell_46_57 255 "Invalid" ;
VAL_ 2400382585 CSC_Tcell_47_57 255 "Invalid" ;
VAL_ 2400382585 CSC_Tcell_48_57 255 "Invalid" ;
VAL_ 2400382585 CSC_Tcell_49_57 255 "Invalid" ;
VAL_ 2400382585 CSC_Tcell_50_57 255 "Invalid" ;
VAL_ 2400382585 CSC_Tcell_51_57 255 "Invalid" ;
VAL_ 2400382585 CSC_Tcell_52_57 255 "Invalid" ;
VAL_ 2400382585 CSC_Tcell_53_57 255 "Invalid" ;
VAL_ 2400382585 CSC_Tcell_54_57 255 "Invalid" ;
VAL_ 2400382585 CSC_Tcell_55_57 255 "Invalid" ;
VAL_ 2400382585 CSC_Tcell_56_57 255 "Invalid" ;
VAL_ 2400382585 CSC_Tcell_57_57 255 "Invalid" ;
VAL_ 2400382585 CSC_Tcell_58_57 255 "Invalid" ;
VAL_ 2400382585 CSC_Tcell_59_57 255 "Invalid" ;
VAL_ 2400382585 CSC_Tcell_60_57 255 "Invalid" ;
VAL_ 2400382585 CSC_Tcell_61_57 255 "Invalid" ;
VAL_ 2400382585 CSC_Tcell_62_57 255 "Invalid" ;
VAL_ 2400382585 CSC_Tcell_63_57 255 "Invalid" ;
VAL_ 2400382585 CSC_Tcell_64_57 255 "Invalid" ;
VAL_ 2400382585 CSC_Tcell_65_57 255 "Invalid" ;
VAL_ 2400382585 CSC_Tcell_66_57 255 "Invalid" ;
VAL_ 2400382585 CSC_Tcell_67_57 255 "Invalid" ;
VAL_ 2400382585 CSC_Tcell_68_57 255 "Invalid" ;
VAL_ 2400382585 CSC_Tcell_69_57 255 "Invalid" ;
VAL_ 2400382585 CSC_Tcell_70_57 255 "Invalid" ;
VAL_ 2400382585 CSC_Tcell_71_57 255 "Invalid" ;
VAL_ 2400382585 CSC_Tcell_72_57 255 "Invalid" ;
VAL_ 2400382586 CSC_T_No_58 1 "CSC 1" 2 "CSC 2" 3 "CSC 3" 4 "CSC 4" 5 "CSC 5" 6 "CSC 6" ;
VAL_ 2400382586 CSC_Tcell_01_58 255 "Invalid" ;
VAL_ 2400382586 CSC_Tcell_02_58 255 "Invalid" ;
VAL_ 2400382586 CSC_Tcell_03_58 255 "Invalid" ;
VAL_ 2400382586 CSC_Tcell_04_58 255 "Invalid" ;
VAL_ 2400382586 CSC_Tcell_05_58 255 "Invalid" ;
VAL_ 2400382586 CSC_Tcell_06_58 255 "Invalid" ;
VAL_ 2400382586 CSC_Tcell_07_58 255 "Invalid" ;
VAL_ 2400382586 CSC_Tcell_08_58 255 "Invalid" ;
VAL_ 2400382586 CSC_Tcell_09_58 255 "Invalid" ;
VAL_ 2400382586 CSC_Tcell_10_58 255 "Invalid" ;
VAL_ 2400382586 CSC_Tcell_11_58 255 "Invalid" ;
VAL_ 2400382586 CSC_Tcell_12_58 255 "Invalid" ;
VAL_ 2400382586 CSC_Tcell_13_58 255 "Invalid" ;
VAL_ 2400382586 CSC_Tcell_14_58 255 "Invalid" ;
VAL_ 2400382586 CSC_Tcell_15_58 255 "Invalid" ;
VAL_ 2400382586 CSC_Tcell_16_58 255 "Invalid" ;
VAL_ 2400382586 CSC_Tcell_17_58 255 "Invalid" ;
VAL_ 2400382586 CSC_Tcell_18_58 255 "Invalid" ;
VAL_ 2400382586 CSC_Tcell_19_58 255 "Invalid" ;
VAL_ 2400382586 CSC_Tcell_20_58 255 "Invalid" ;
VAL_ 2400382586 CSC_Tcell_21_58 255 "Invalid" ;
VAL_ 2400382586 CSC_Tcell_22_58 255 "Invalid" ;
VAL_ 2400382586 CSC_Tcell_23_58 255 "Invalid" ;
VAL_ 2400382586 CSC_Tcell_24_58 255 "Invalid" ;
VAL_ 2400382586 CSC_Tcell_25_58 255 "Invalid" ;
VAL_ 2400382586 CSC_Tcell_26_58 255 "Invalid" ;
VAL_ 2400382586 CSC_Tcell_27_58 255 "Invalid" ;
VAL_ 2400382586 CSC_Tcell_28_58 255 "Invalid" ;
VAL_ 2400382586 CSC_Tcell_29_58 255 "Invalid" ;
VAL_ 2400382586 CSC_Tcell_30_58 255 "Invalid" ;
VAL_ 2400382586 CSC_Tcell_31_58 255 "Invalid" ;
VAL_ 2400382586 CSC_Tcell_32_58 255 "Invalid" ;
VAL_ 2400382586 CSC_Tcell_33_58 255 "Invalid" ;
VAL_ 2400382586 CSC_Tcell_34_58 255 "Invalid" ;
VAL_ 2400382586 CSC_Tcell_35_58 255 "Invalid" ;
VAL_ 2400382586 CSC_Tcell_36_58 255 "Invalid" ;
VAL_ 2400382586 CSC_Tcell_37_58 255 "Invalid" ;
VAL_ 2400382586 CSC_Tcell_38_58 255 "Invalid" ;
VAL_ 2400382586 CSC_Tcell_39_58 255 "Invalid" ;
VAL_ 2400382586 CSC_Tcell_40_58 255 "Invalid" ;
VAL_ 2400382586 CSC_Tcell_41_58 255 "Invalid" ;
VAL_ 2400382586 CSC_Tcell_42_58 255 "Invalid" ;
VAL_ 2400382586 CSC_Tcell_43_58 255 "Invalid" ;
VAL_ 2400382586 CSC_Tcell_44_58 255 "Invalid" ;
VAL_ 2400382586 CSC_Tcell_45_58 255 "Invalid" ;
VAL_ 2400382586 CSC_Tcell_46_58 255 "Invalid" ;
VAL_ 2400382586 CSC_Tcell_47_58 255 "Invalid" ;
VAL_ 2400382586 CSC_Tcell_48_58 255 "Invalid" ;
VAL_ 2400382586 CSC_Tcell_49_58 255 "Invalid" ;
VAL_ 2400382586 CSC_Tcell_50_58 255 "Invalid" ;
VAL_ 2400382586 CSC_Tcell_51_58 255 "Invalid" ;
VAL_ 2400382586 CSC_Tcell_52_58 255 "Invalid" ;
VAL_ 2400382586 CSC_Tcell_53_58 255 "Invalid" ;
VAL_ 2400382586 CSC_Tcell_54_58 255 "Invalid" ;
VAL_ 2400382586 CSC_Tcell_55_58 255 "Invalid" ;
VAL_ 2400382586 CSC_Tcell_56_58 255 "Invalid" ;
VAL_ 2400382586 CSC_Tcell_57_58 255 "Invalid" ;
VAL_ 2400382586 CSC_Tcell_58_58 255 "Invalid" ;
VAL_ 2400382586 CSC_Tcell_59_58 255 "Invalid" ;
VAL_ 2400382586 CSC_Tcell_60_58 255 "Invalid" ;
VAL_ 2400382586 CSC_Tcell_61_58 255 "Invalid" ;
VAL_ 2400382586 CSC_Tcell_62_58 255 "Invalid" ;
VAL_ 2400382586 CSC_Tcell_63_58 255 "Invalid" ;
VAL_ 2400382586 CSC_Tcell_64_58 255 "Invalid" ;
VAL_ 2400382586 CSC_Tcell_65_58 255 "Invalid" ;
VAL_ 2400382586 CSC_Tcell_66_58 255 "Invalid" ;
VAL_ 2400382586 CSC_Tcell_67_58 255 "Invalid" ;
VAL_ 2400382586 CSC_Tcell_68_58 255 "Invalid" ;
VAL_ 2400382586 CSC_Tcell_69_58 255 "Invalid" ;
VAL_ 2400382586 CSC_Tcell_70_58 255 "Invalid" ;
VAL_ 2400382586 CSC_Tcell_71_58 255 "Invalid" ;
VAL_ 2400382586 CSC_Tcell_72_58 255 "Invalid" ;
VAL_ 2400382587 CSC_T_No_59 1 "CSC 1" 2 "CSC 2" 3 "CSC 3" 4 "CSC 4" 5 "CSC 5" 6 "CSC 6" ;
VAL_ 2400382587 CSC_Tcell_01_59 255 "Invalid" ;
VAL_ 2400382587 CSC_Tcell_02_59 255 "Invalid" ;
VAL_ 2400382587 CSC_Tcell_03_59 255 "Invalid" ;
VAL_ 2400382587 CSC_Tcell_04_59 255 "Invalid" ;
VAL_ 2400382587 CSC_Tcell_05_59 255 "Invalid" ;
VAL_ 2400382587 CSC_Tcell_06_59 255 "Invalid" ;
VAL_ 2400382587 CSC_Tcell_07_59 255 "Invalid" ;
VAL_ 2400382587 CSC_Tcell_08_59 255 "Invalid" ;
VAL_ 2400382587 CSC_Tcell_09_59 255 "Invalid" ;
VAL_ 2400382587 CSC_Tcell_10_59 255 "Invalid" ;
VAL_ 2400382587 CSC_Tcell_11_59 255 "Invalid" ;
VAL_ 2400382587 CSC_Tcell_12_59 255 "Invalid" ;
VAL_ 2400382587 CSC_Tcell_13_59 255 "Invalid" ;
VAL_ 2400382587 CSC_Tcell_14_59 255 "Invalid" ;
VAL_ 2400382587 CSC_Tcell_15_59 255 "Invalid" ;
VAL_ 2400382587 CSC_Tcell_16_59 255 "Invalid" ;
VAL_ 2400382587 CSC_Tcell_17_59 255 "Invalid" ;
VAL_ 2400382587 CSC_Tcell_18_59 255 "Invalid" ;
VAL_ 2400382587 CSC_Tcell_19_59 255 "Invalid" ;
VAL_ 2400382587 CSC_Tcell_20_59 255 "Invalid" ;
VAL_ 2400382587 CSC_Tcell_21_59 255 "Invalid" ;
VAL_ 2400382587 CSC_Tcell_22_59 255 "Invalid" ;
VAL_ 2400382587 CSC_Tcell_23_59 255 "Invalid" ;
VAL_ 2400382587 CSC_Tcell_24_59 255 "Invalid" ;
VAL_ 2400382587 CSC_Tcell_25_59 255 "Invalid" ;
VAL_ 2400382587 CSC_Tcell_26_59 255 "Invalid" ;
VAL_ 2400382587 CSC_Tcell_27_59 255 "Invalid" ;
VAL_ 2400382587 CSC_Tcell_28_59 255 "Invalid" ;
VAL_ 2400382587 CSC_Tcell_29_59 255 "Invalid" ;
VAL_ 2400382587 CSC_Tcell_30_59 255 "Invalid" ;
VAL_ 2400382587 CSC_Tcell_31_59 255 "Invalid" ;
VAL_ 2400382587 CSC_Tcell_32_59 255 "Invalid" ;
VAL_ 2400382587 CSC_Tcell_33_59 255 "Invalid" ;
VAL_ 2400382587 CSC_Tcell_34_59 255 "Invalid" ;
VAL_ 2400382587 CSC_Tcell_35_59 255 "Invalid" ;
VAL_ 2400382587 CSC_Tcell_36_59 255 "Invalid" ;
VAL_ 2400382587 CSC_Tcell_37_59 255 "Invalid" ;
VAL_ 2400382587 CSC_Tcell_38_59 255 "Invalid" ;
VAL_ 2400382587 CSC_Tcell_39_59 255 "Invalid" ;
VAL_ 2400382587 CSC_Tcell_40_59 255 "Invalid" ;
VAL_ 2400382587 CSC_Tcell_41_59 255 "Invalid" ;
VAL_ 2400382587 CSC_Tcell_42_59 255 "Invalid" ;
VAL_ 2400382587 CSC_Tcell_43_59 255 "Invalid" ;
VAL_ 2400382587 CSC_Tcell_44_59 255 "Invalid" ;
VAL_ 2400382587 CSC_Tcell_45_59 255 "Invalid" ;
VAL_ 2400382587 CSC_Tcell_46_59 255 "Invalid" ;
VAL_ 2400382587 CSC_Tcell_47_59 255 "Invalid" ;
VAL_ 2400382587 CSC_Tcell_48_59 255 "Invalid" ;
VAL_ 2400382587 CSC_Tcell_49_59 255 "Invalid" ;
VAL_ 2400382587 CSC_Tcell_50_59 255 "Invalid" ;
VAL_ 2400382587 CSC_Tcell_51_59 255 "Invalid" ;
VAL_ 2400382587 CSC_Tcell_52_59 255 "Invalid" ;
VAL_ 2400382587 CSC_Tcell_53_59 255 "Invalid" ;
VAL_ 2400382587 CSC_Tcell_54_59 255 "Invalid" ;
VAL_ 2400382587 CSC_Tcell_55_59 255 "Invalid" ;
VAL_ 2400382587 CSC_Tcell_56_59 255 "Invalid" ;
VAL_ 2400382587 CSC_Tcell_57_59 255 "Invalid" ;
VAL_ 2400382587 CSC_Tcell_58_59 255 "Invalid" ;
VAL_ 2400382587 CSC_Tcell_59_59 255 "Invalid" ;
VAL_ 2400382587 CSC_Tcell_60_59 255 "Invalid" ;
VAL_ 2400382587 CSC_Tcell_61_59 255 "Invalid" ;
VAL_ 2400382587 CSC_Tcell_62_59 255 "Invalid" ;
VAL_ 2400382587 CSC_Tcell_63_59 255 "Invalid" ;
VAL_ 2400382587 CSC_Tcell_64_59 255 "Invalid" ;
VAL_ 2400382587 CSC_Tcell_65_59 255 "Invalid" ;
VAL_ 2400382587 CSC_Tcell_66_59 255 "Invalid" ;
VAL_ 2400382587 CSC_Tcell_67_59 255 "Invalid" ;
VAL_ 2400382587 CSC_Tcell_68_59 255 "Invalid" ;
VAL_ 2400382587 CSC_Tcell_69_59 255 "Invalid" ;
VAL_ 2400382587 CSC_Tcell_70_59 255 "Invalid" ;
VAL_ 2400382587 CSC_Tcell_71_59 255 "Invalid" ;
VAL_ 2400382587 CSC_Tcell_72_59 255 "Invalid" ;
VAL_ 2400382588 CSC_T_No_60 1 "CSC 1" 2 "CSC 2" 3 "CSC 3" 4 "CSC 4" 5 "CSC 5" 6 "CSC 6" ;
VAL_ 2400382588 CSC_Tcell_01_60 255 "Invalid" ;
VAL_ 2400382588 CSC_Tcell_02_60 255 "Invalid" ;
VAL_ 2400382588 CSC_Tcell_03_60 255 "Invalid" ;
VAL_ 2400382588 CSC_Tcell_04_60 255 "Invalid" ;
VAL_ 2400382588 CSC_Tcell_05_60 255 "Invalid" ;
VAL_ 2400382588 CSC_Tcell_06_60 255 "Invalid" ;
VAL_ 2400382588 CSC_Tcell_07_60 255 "Invalid" ;
VAL_ 2400382588 CSC_Tcell_08_60 255 "Invalid" ;
VAL_ 2400382588 CSC_Tcell_09_60 255 "Invalid" ;
VAL_ 2400382588 CSC_Tcell_10_60 255 "Invalid" ;
VAL_ 2400382588 CSC_Tcell_11_60 255 "Invalid" ;
VAL_ 2400382588 CSC_Tcell_12_60 255 "Invalid" ;
VAL_ 2400382588 CSC_Tcell_13_60 255 "Invalid" ;
VAL_ 2400382588 CSC_Tcell_14_60 255 "Invalid" ;
VAL_ 2400382588 CSC_Tcell_15_60 255 "Invalid" ;
VAL_ 2400382588 CSC_Tcell_16_60 255 "Invalid" ;
VAL_ 2400382588 CSC_Tcell_17_60 255 "Invalid" ;
VAL_ 2400382588 CSC_Tcell_18_60 255 "Invalid" ;
VAL_ 2400382588 CSC_Tcell_19_60 255 "Invalid" ;
VAL_ 2400382588 CSC_Tcell_20_60 255 "Invalid" ;
VAL_ 2400382588 CSC_Tcell_21_60 255 "Invalid" ;
VAL_ 2400382588 CSC_Tcell_22_60 255 "Invalid" ;
VAL_ 2400382588 CSC_Tcell_23_60 255 "Invalid" ;
VAL_ 2400382588 CSC_Tcell_24_60 255 "Invalid" ;
VAL_ 2400382588 CSC_Tcell_25_60 255 "Invalid" ;
VAL_ 2400382588 CSC_Tcell_26_60 255 "Invalid" ;
VAL_ 2400382588 CSC_Tcell_27_60 255 "Invalid" ;
VAL_ 2400382588 CSC_Tcell_28_60 255 "Invalid" ;
VAL_ 2400382588 CSC_Tcell_29_60 255 "Invalid" ;
VAL_ 2400382588 CSC_Tcell_30_60 255 "Invalid" ;
VAL_ 2400382588 CSC_Tcell_31_60 255 "Invalid" ;
VAL_ 2400382588 CSC_Tcell_32_60 255 "Invalid" ;
VAL_ 2400382588 CSC_Tcell_33_60 255 "Invalid" ;
VAL_ 2400382588 CSC_Tcell_34_60 255 "Invalid" ;
VAL_ 2400382588 CSC_Tcell_35_60 255 "Invalid" ;
VAL_ 2400382588 CSC_Tcell_36_60 255 "Invalid" ;
VAL_ 2400382588 CSC_Tcell_37_60 255 "Invalid" ;
VAL_ 2400382588 CSC_Tcell_38_60 255 "Invalid" ;
VAL_ 2400382588 CSC_Tcell_39_60 255 "Invalid" ;
VAL_ 2400382588 CSC_Tcell_40_60 255 "Invalid" ;
VAL_ 2400382588 CSC_Tcell_41_60 255 "Invalid" ;
VAL_ 2400382588 CSC_Tcell_42_60 255 "Invalid" ;
VAL_ 2400382588 CSC_Tcell_43_60 255 "Invalid" ;
VAL_ 2400382588 CSC_Tcell_44_60 255 "Invalid" ;
VAL_ 2400382588 CSC_Tcell_45_60 255 "Invalid" ;
VAL_ 2400382588 CSC_Tcell_46_60 255 "Invalid" ;
VAL_ 2400382588 CSC_Tcell_47_60 255 "Invalid" ;
VAL_ 2400382588 CSC_Tcell_48_60 255 "Invalid" ;
VAL_ 2400382588 CSC_Tcell_49_60 255 "Invalid" ;
VAL_ 2400382588 CSC_Tcell_50_60 255 "Invalid" ;
VAL_ 2400382588 CSC_Tcell_51_60 255 "Invalid" ;
VAL_ 2400382588 CSC_Tcell_52_60 255 "Invalid" ;
VAL_ 2400382588 CSC_Tcell_53_60 255 "Invalid" ;
VAL_ 2400382588 CSC_Tcell_54_60 255 "Invalid" ;
VAL_ 2400382588 CSC_Tcell_55_60 255 "Invalid" ;
VAL_ 2400382588 CSC_Tcell_56_60 255 "Invalid" ;
VAL_ 2400382588 CSC_Tcell_57_60 255 "Invalid" ;
VAL_ 2400382588 CSC_Tcell_58_60 255 "Invalid" ;
VAL_ 2400382588 CSC_Tcell_59_60 255 "Invalid" ;
VAL_ 2400382588 CSC_Tcell_60_60 255 "Invalid" ;
VAL_ 2400382588 CSC_Tcell_61_60 255 "Invalid" ;
VAL_ 2400382588 CSC_Tcell_62_60 255 "Invalid" ;
VAL_ 2400382588 CSC_Tcell_63_60 255 "Invalid" ;
VAL_ 2400382588 CSC_Tcell_64_60 255 "Invalid" ;
VAL_ 2400382588 CSC_Tcell_65_60 255 "Invalid" ;
VAL_ 2400382588 CSC_Tcell_66_60 255 "Invalid" ;
VAL_ 2400382588 CSC_Tcell_67_60 255 "Invalid" ;
VAL_ 2400382588 CSC_Tcell_68_60 255 "Invalid" ;
VAL_ 2400382588 CSC_Tcell_69_60 255 "Invalid" ;
VAL_ 2400382588 CSC_Tcell_70_60 255 "Invalid" ;
VAL_ 2400382588 CSC_Tcell_71_60 255 "Invalid" ;
VAL_ 2400382588 CSC_Tcell_72_60 255 "Invalid" ;
VAL_ 2400382589 CSC_T_No_61 1 "CSC 1" 2 "CSC 2" 3 "CSC 3" 4 "CSC 4" 5 "CSC 5" 6 "CSC 6" ;
VAL_ 2400382589 CSC_Tcell_01_61 255 "Invalid" ;
VAL_ 2400382589 CSC_Tcell_02_61 255 "Invalid" ;
VAL_ 2400382589 CSC_Tcell_03_61 255 "Invalid" ;
VAL_ 2400382589 CSC_Tcell_04_61 255 "Invalid" ;
VAL_ 2400382589 CSC_Tcell_05_61 255 "Invalid" ;
VAL_ 2400382589 CSC_Tcell_06_61 255 "Invalid" ;
VAL_ 2400382589 CSC_Tcell_07_61 255 "Invalid" ;
VAL_ 2400382589 CSC_Tcell_08_61 255 "Invalid" ;
VAL_ 2400382589 CSC_Tcell_09_61 255 "Invalid" ;
VAL_ 2400382589 CSC_Tcell_10_61 255 "Invalid" ;
VAL_ 2400382589 CSC_Tcell_11_61 255 "Invalid" ;
VAL_ 2400382589 CSC_Tcell_12_61 255 "Invalid" ;
VAL_ 2400382589 CSC_Tcell_13_61 255 "Invalid" ;
VAL_ 2400382589 CSC_Tcell_14_61 255 "Invalid" ;
VAL_ 2400382589 CSC_Tcell_15_61 255 "Invalid" ;
VAL_ 2400382589 CSC_Tcell_16_61 255 "Invalid" ;
VAL_ 2400382589 CSC_Tcell_17_61 255 "Invalid" ;
VAL_ 2400382589 CSC_Tcell_18_61 255 "Invalid" ;
VAL_ 2400382589 CSC_Tcell_19_61 255 "Invalid" ;
VAL_ 2400382589 CSC_Tcell_20_61 255 "Invalid" ;
VAL_ 2400382589 CSC_Tcell_21_61 255 "Invalid" ;
VAL_ 2400382589 CSC_Tcell_22_61 255 "Invalid" ;
VAL_ 2400382589 CSC_Tcell_23_61 255 "Invalid" ;
VAL_ 2400382589 CSC_Tcell_24_61 255 "Invalid" ;
VAL_ 2400382589 CSC_Tcell_25_61 255 "Invalid" ;
VAL_ 2400382589 CSC_Tcell_26_61 255 "Invalid" ;
VAL_ 2400382589 CSC_Tcell_27_61 255 "Invalid" ;
VAL_ 2400382589 CSC_Tcell_28_61 255 "Invalid" ;
VAL_ 2400382589 CSC_Tcell_29_61 255 "Invalid" ;
VAL_ 2400382589 CSC_Tcell_30_61 255 "Invalid" ;
VAL_ 2400382589 CSC_Tcell_31_61 255 "Invalid" ;
VAL_ 2400382589 CSC_Tcell_32_61 255 "Invalid" ;
VAL_ 2400382589 CSC_Tcell_33_61 255 "Invalid" ;
VAL_ 2400382589 CSC_Tcell_34_61 255 "Invalid" ;
VAL_ 2400382589 CSC_Tcell_35_61 255 "Invalid" ;
VAL_ 2400382589 CSC_Tcell_36_61 255 "Invalid" ;
VAL_ 2400382589 CSC_Tcell_37_61 255 "Invalid" ;
VAL_ 2400382589 CSC_Tcell_38_61 255 "Invalid" ;
VAL_ 2400382589 CSC_Tcell_39_61 255 "Invalid" ;
VAL_ 2400382589 CSC_Tcell_40_61 255 "Invalid" ;
VAL_ 2400382589 CSC_Tcell_41_61 255 "Invalid" ;
VAL_ 2400382589 CSC_Tcell_42_61 255 "Invalid" ;
VAL_ 2400382589 CSC_Tcell_43_61 255 "Invalid" ;
VAL_ 2400382589 CSC_Tcell_44_61 255 "Invalid" ;
VAL_ 2400382589 CSC_Tcell_45_61 255 "Invalid" ;
VAL_ 2400382589 CSC_Tcell_46_61 255 "Invalid" ;
VAL_ 2400382589 CSC_Tcell_47_61 255 "Invalid" ;
VAL_ 2400382589 CSC_Tcell_48_61 255 "Invalid" ;
VAL_ 2400382589 CSC_Tcell_49_61 255 "Invalid" ;
VAL_ 2400382589 CSC_Tcell_50_61 255 "Invalid" ;
VAL_ 2400382589 CSC_Tcell_51_61 255 "Invalid" ;
VAL_ 2400382589 CSC_Tcell_52_61 255 "Invalid" ;
VAL_ 2400382589 CSC_Tcell_53_61 255 "Invalid" ;
VAL_ 2400382589 CSC_Tcell_54_61 255 "Invalid" ;
VAL_ 2400382589 CSC_Tcell_55_61 255 "Invalid" ;
VAL_ 2400382589 CSC_Tcell_56_61 255 "Invalid" ;
VAL_ 2400382589 CSC_Tcell_57_61 255 "Invalid" ;
VAL_ 2400382589 CSC_Tcell_58_61 255 "Invalid" ;
VAL_ 2400382589 CSC_Tcell_59_61 255 "Invalid" ;
VAL_ 2400382589 CSC_Tcell_60_61 255 "Invalid" ;
VAL_ 2400382589 CSC_Tcell_61_61 255 "Invalid" ;
VAL_ 2400382589 CSC_Tcell_62_61 255 "Invalid" ;
VAL_ 2400382589 CSC_Tcell_63_61 255 "Invalid" ;
VAL_ 2400382589 CSC_Tcell_64_61 255 "Invalid" ;
VAL_ 2400382589 CSC_Tcell_65_61 255 "Invalid" ;
VAL_ 2400382589 CSC_Tcell_66_61 255 "Invalid" ;
VAL_ 2400382589 CSC_Tcell_67_61 255 "Invalid" ;
VAL_ 2400382589 CSC_Tcell_68_61 255 "Invalid" ;
VAL_ 2400382589 CSC_Tcell_69_61 255 "Invalid" ;
VAL_ 2400382589 CSC_Tcell_70_61 255 "Invalid" ;
VAL_ 2400382589 CSC_Tcell_71_61 255 "Invalid" ;
VAL_ 2400382589 CSC_Tcell_72_61 255 "Invalid" ;
VAL_ 2400382590 CSC_T_No_62 1 "CSC 1" 2 "CSC 2" 3 "CSC 3" 4 "CSC 4" 5 "CSC 5" 6 "CSC 6" ;
VAL_ 2400382590 CSC_Tcell_01_62 255 "Invalid" ;
VAL_ 2400382590 CSC_Tcell_02_62 255 "Invalid" ;
VAL_ 2400382590 CSC_Tcell_03_62 255 "Invalid" ;
VAL_ 2400382590 CSC_Tcell_04_62 255 "Invalid" ;
VAL_ 2400382590 CSC_Tcell_05_62 255 "Invalid" ;
VAL_ 2400382590 CSC_Tcell_06_62 255 "Invalid" ;
VAL_ 2400382590 CSC_Tcell_07_62 255 "Invalid" ;
VAL_ 2400382590 CSC_Tcell_08_62 255 "Invalid" ;
VAL_ 2400382590 CSC_Tcell_09_62 255 "Invalid" ;
VAL_ 2400382590 CSC_Tcell_10_62 255 "Invalid" ;
VAL_ 2400382590 CSC_Tcell_11_62 255 "Invalid" ;
VAL_ 2400382590 CSC_Tcell_12_62 255 "Invalid" ;
VAL_ 2400382590 CSC_Tcell_13_62 255 "Invalid" ;
VAL_ 2400382590 CSC_Tcell_14_62 255 "Invalid" ;
VAL_ 2400382590 CSC_Tcell_15_62 255 "Invalid" ;
VAL_ 2400382590 CSC_Tcell_16_62 255 "Invalid" ;
VAL_ 2400382590 CSC_Tcell_17_62 255 "Invalid" ;
VAL_ 2400382590 CSC_Tcell_18_62 255 "Invalid" ;
VAL_ 2400382590 CSC_Tcell_19_62 255 "Invalid" ;
VAL_ 2400382590 CSC_Tcell_20_62 255 "Invalid" ;
VAL_ 2400382590 CSC_Tcell_21_62 255 "Invalid" ;
VAL_ 2400382590 CSC_Tcell_22_62 255 "Invalid" ;
VAL_ 2400382590 CSC_Tcell_23_62 255 "Invalid" ;
VAL_ 2400382590 CSC_Tcell_24_62 255 "Invalid" ;
VAL_ 2400382590 CSC_Tcell_25_62 255 "Invalid" ;
VAL_ 2400382590 CSC_Tcell_26_62 255 "Invalid" ;
VAL_ 2400382590 CSC_Tcell_27_62 255 "Invalid" ;
VAL_ 2400382590 CSC_Tcell_28_62 255 "Invalid" ;
VAL_ 2400382590 CSC_Tcell_29_62 255 "Invalid" ;
VAL_ 2400382590 CSC_Tcell_30_62 255 "Invalid" ;
VAL_ 2400382590 CSC_Tcell_31_62 255 "Invalid" ;
VAL_ 2400382590 CSC_Tcell_32_62 255 "Invalid" ;
VAL_ 2400382590 CSC_Tcell_33_62 255 "Invalid" ;
VAL_ 2400382590 CSC_Tcell_34_62 255 "Invalid" ;
VAL_ 2400382590 CSC_Tcell_35_62 255 "Invalid" ;
VAL_ 2400382590 CSC_Tcell_36_62 255 "Invalid" ;
VAL_ 2400382590 CSC_Tcell_37_62 255 "Invalid" ;
VAL_ 2400382590 CSC_Tcell_38_62 255 "Invalid" ;
VAL_ 2400382590 CSC_Tcell_39_62 255 "Invalid" ;
VAL_ 2400382590 CSC_Tcell_40_62 255 "Invalid" ;
VAL_ 2400382590 CSC_Tcell_41_62 255 "Invalid" ;
VAL_ 2400382590 CSC_Tcell_42_62 255 "Invalid" ;
VAL_ 2400382590 CSC_Tcell_43_62 255 "Invalid" ;
VAL_ 2400382590 CSC_Tcell_44_62 255 "Invalid" ;
VAL_ 2400382590 CSC_Tcell_45_62 255 "Invalid" ;
VAL_ 2400382590 CSC_Tcell_46_62 255 "Invalid" ;
VAL_ 2400382590 CSC_Tcell_47_62 255 "Invalid" ;
VAL_ 2400382590 CSC_Tcell_48_62 255 "Invalid" ;
VAL_ 2400382590 CSC_Tcell_49_62 255 "Invalid" ;
VAL_ 2400382590 CSC_Tcell_50_62 255 "Invalid" ;
VAL_ 2400382590 CSC_Tcell_51_62 255 "Invalid" ;
VAL_ 2400382590 CSC_Tcell_52_62 255 "Invalid" ;
VAL_ 2400382590 CSC_Tcell_53_62 255 "Invalid" ;
VAL_ 2400382590 CSC_Tcell_54_62 255 "Invalid" ;
VAL_ 2400382590 CSC_Tcell_55_62 255 "Invalid" ;
VAL_ 2400382590 CSC_Tcell_56_62 255 "Invalid" ;
VAL_ 2400382590 CSC_Tcell_57_62 255 "Invalid" ;
VAL_ 2400382590 CSC_Tcell_58_62 255 "Invalid" ;
VAL_ 2400382590 CSC_Tcell_59_62 255 "Invalid" ;
VAL_ 2400382590 CSC_Tcell_60_62 255 "Invalid" ;
VAL_ 2400382590 CSC_Tcell_61_62 255 "Invalid" ;
VAL_ 2400382590 CSC_Tcell_62_62 255 "Invalid" ;
VAL_ 2400382590 CSC_Tcell_63_62 255 "Invalid" ;
VAL_ 2400382590 CSC_Tcell_64_62 255 "Invalid" ;
VAL_ 2400382590 CSC_Tcell_65_62 255 "Invalid" ;
VAL_ 2400382590 CSC_Tcell_66_62 255 "Invalid" ;
VAL_ 2400382590 CSC_Tcell_67_62 255 "Invalid" ;
VAL_ 2400382590 CSC_Tcell_68_62 255 "Invalid" ;
VAL_ 2400382590 CSC_Tcell_69_62 255 "Invalid" ;
VAL_ 2400382590 CSC_Tcell_70_62 255 "Invalid" ;
VAL_ 2400382590 CSC_Tcell_71_62 255 "Invalid" ;
VAL_ 2400382590 CSC_Tcell_72_62 255 "Invalid" ;
VAL_ 2400382591 CSC_T_No_63 1 "CSC 1" 2 "CSC 2" 3 "CSC 3" 4 "CSC 4" 5 "CSC 5" 6 "CSC 6" ;
VAL_ 2400382591 CSC_Tcell_01_63 255 "Invalid" ;
VAL_ 2400382591 CSC_Tcell_02_63 255 "Invalid" ;
VAL_ 2400382591 CSC_Tcell_03_63 255 "Invalid" ;
VAL_ 2400382591 CSC_Tcell_04_63 255 "Invalid" ;
VAL_ 2400382591 CSC_Tcell_05_63 255 "Invalid" ;
VAL_ 2400382591 CSC_Tcell_06_63 255 "Invalid" ;
VAL_ 2400382591 CSC_Tcell_07_63 255 "Invalid" ;
VAL_ 2400382591 CSC_Tcell_08_63 255 "Invalid" ;
VAL_ 2400382591 CSC_Tcell_09_63 255 "Invalid" ;
VAL_ 2400382591 CSC_Tcell_10_63 255 "Invalid" ;
VAL_ 2400382591 CSC_Tcell_11_63 255 "Invalid" ;
VAL_ 2400382591 CSC_Tcell_12_63 255 "Invalid" ;
VAL_ 2400382591 CSC_Tcell_13_63 255 "Invalid" ;
VAL_ 2400382591 CSC_Tcell_14_63 255 "Invalid" ;
VAL_ 2400382591 CSC_Tcell_15_63 255 "Invalid" ;
VAL_ 2400382591 CSC_Tcell_16_63 255 "Invalid" ;
VAL_ 2400382591 CSC_Tcell_17_63 255 "Invalid" ;
VAL_ 2400382591 CSC_Tcell_18_63 255 "Invalid" ;
VAL_ 2400382591 CSC_Tcell_19_63 255 "Invalid" ;
VAL_ 2400382591 CSC_Tcell_20_63 255 "Invalid" ;
VAL_ 2400382591 CSC_Tcell_21_63 255 "Invalid" ;
VAL_ 2400382591 CSC_Tcell_22_63 255 "Invalid" ;
VAL_ 2400382591 CSC_Tcell_23_63 255 "Invalid" ;
VAL_ 2400382591 CSC_Tcell_24_63 255 "Invalid" ;
VAL_ 2400382591 CSC_Tcell_25_63 255 "Invalid" ;
VAL_ 2400382591 CSC_Tcell_26_63 255 "Invalid" ;
VAL_ 2400382591 CSC_Tcell_27_63 255 "Invalid" ;
VAL_ 2400382591 CSC_Tcell_28_63 255 "Invalid" ;
VAL_ 2400382591 CSC_Tcell_29_63 255 "Invalid" ;
VAL_ 2400382591 CSC_Tcell_30_63 255 "Invalid" ;
VAL_ 2400382591 CSC_Tcell_31_63 255 "Invalid" ;
VAL_ 2400382591 CSC_Tcell_32_63 255 "Invalid" ;
VAL_ 2400382591 CSC_Tcell_33_63 255 "Invalid" ;
VAL_ 2400382591 CSC_Tcell_34_63 255 "Invalid" ;
VAL_ 2400382591 CSC_Tcell_35_63 255 "Invalid" ;
VAL_ 2400382591 CSC_Tcell_36_63 255 "Invalid" ;
VAL_ 2400382591 CSC_Tcell_37_63 255 "Invalid" ;
VAL_ 2400382591 CSC_Tcell_38_63 255 "Invalid" ;
VAL_ 2400382591 CSC_Tcell_39_63 255 "Invalid" ;
VAL_ 2400382591 CSC_Tcell_40_63 255 "Invalid" ;
VAL_ 2400382591 CSC_Tcell_41_63 255 "Invalid" ;
VAL_ 2400382591 CSC_Tcell_42_63 255 "Invalid" ;
VAL_ 2400382591 CSC_Tcell_43_63 255 "Invalid" ;
VAL_ 2400382591 CSC_Tcell_44_63 255 "Invalid" ;
VAL_ 2400382591 CSC_Tcell_45_63 255 "Invalid" ;
VAL_ 2400382591 CSC_Tcell_46_63 255 "Invalid" ;
VAL_ 2400382591 CSC_Tcell_47_63 255 "Invalid" ;
VAL_ 2400382591 CSC_Tcell_48_63 255 "Invalid" ;
VAL_ 2400382591 CSC_Tcell_49_63 255 "Invalid" ;
VAL_ 2400382591 CSC_Tcell_50_63 255 "Invalid" ;
VAL_ 2400382591 CSC_Tcell_51_63 255 "Invalid" ;
VAL_ 2400382591 CSC_Tcell_52_63 255 "Invalid" ;
VAL_ 2400382591 CSC_Tcell_53_63 255 "Invalid" ;
VAL_ 2400382591 CSC_Tcell_54_63 255 "Invalid" ;
VAL_ 2400382591 CSC_Tcell_55_63 255 "Invalid" ;
VAL_ 2400382591 CSC_Tcell_56_63 255 "Invalid" ;
VAL_ 2400382591 CSC_Tcell_57_63 255 "Invalid" ;
VAL_ 2400382591 CSC_Tcell_58_63 255 "Invalid" ;
VAL_ 2400382591 CSC_Tcell_59_63 255 "Invalid" ;
VAL_ 2400382591 CSC_Tcell_60_63 255 "Invalid" ;
VAL_ 2400382591 CSC_Tcell_61_63 255 "Invalid" ;
VAL_ 2400382591 CSC_Tcell_62_63 255 "Invalid" ;
VAL_ 2400382591 CSC_Tcell_63_63 255 "Invalid" ;
VAL_ 2400382591 CSC_Tcell_64_63 255 "Invalid" ;
VAL_ 2400382591 CSC_Tcell_65_63 255 "Invalid" ;
VAL_ 2400382591 CSC_Tcell_66_63 255 "Invalid" ;
VAL_ 2400382591 CSC_Tcell_67_63 255 "Invalid" ;
VAL_ 2400382591 CSC_Tcell_68_63 255 "Invalid" ;
VAL_ 2400382591 CSC_Tcell_69_63 255 "Invalid" ;
VAL_ 2400382591 CSC_Tcell_70_63 255 "Invalid" ;
VAL_ 2400382591 CSC_Tcell_71_63 255 "Invalid" ;
VAL_ 2400382591 CSC_Tcell_72_63 255 "Invalid" ;
VAL_ 2400448065 CSC_B_No_01 1 "CSC 1" 2 "CSC 2" 3 "CSC 3" 4 "CSC 4" 5 "CSC 5" 6 "CSC 6" 31 "CSC31" ;
VAL_ 2400448065 BalDchg_PosCellLow_01 0 "No Discharging" 1 "Cell1 Discharging" 2 "Cell2 Discharging" 4 "Cell3 Discharging" 8 "Cell4 Discharging" 16 "Cell5 Discharging" 134217728 "Cell28 Discharging" 268435456 "Cell29 Discharging" ;
VAL_ 2400448065 BalDchg_PosCellHigh_01 0 "No Discharging" 1 "Cell1 Discharging" 2 "Cell2 Discharging" 4 "Cell3 Discharging" 8 "Cell4 Discharging" 16 "Cell5 Discharging" 134217728 "Cell28 Discharging" 268435456 "Cell29 Discharging" ;
VAL_ 2400448066 CSC_B_No_02 1 "CSC 1" 2 "CSC 2" 3 "CSC 3" 4 "CSC 4" 5 "CSC 5" 6 "CSC 6" 31 "CSC31" ;
VAL_ 2400448066 BalDchg_PosCellLow_02 0 "No Discharging" 1 "Cell1 Discharging" 2 "Cell2 Discharging" 4 "Cell3 Discharging" 8 "Cell4 Discharging" 16 "Cell5 Discharging" 134217728 "Cell28 Discharging" 268435456 "Cell29 Discharging" ;
VAL_ 2400448066 BalDchg_PosCellHigh_02 0 "No Discharging" 1 "Cell1 Discharging" 2 "Cell2 Discharging" 4 "Cell3 Discharging" 8 "Cell4 Discharging" 16 "Cell5 Discharging" 134217728 "Cell28 Discharging" 268435456 "Cell29 Discharging" ;
VAL_ 2400448067 CSC_B_No_03 1 "CSC 1" 2 "CSC 2" 3 "CSC 3" 4 "CSC 4" 5 "CSC 5" 6 "CSC 6" 31 "CSC31" ;
VAL_ 2400448067 BalDchg_PosCellLow_03 0 "No Discharging" 1 "Cell1 Discharging" 2 "Cell2 Discharging" 4 "Cell3 Discharging" 8 "Cell4 Discharging" 16 "Cell5 Discharging" 134217728 "Cell28 Discharging" 268435456 "Cell29 Discharging" ;
VAL_ 2400448067 BalDchg_PosCellHigh_03 0 "No Discharging" 1 "Cell1 Discharging" 2 "Cell2 Discharging" 4 "Cell3 Discharging" 8 "Cell4 Discharging" 16 "Cell5 Discharging" 134217728 "Cell28 Discharging" 268435456 "Cell29 Discharging" ;
VAL_ 2400448068 CSC_B_No_04 1 "CSC 1" 2 "CSC 2" 3 "CSC 3" 4 "CSC 4" 5 "CSC 5" 6 "CSC 6" 31 "CSC31" ;
VAL_ 2400448068 BalDchg_PosCellLow_04 0 "No Discharging" 1 "Cell1 Discharging" 2 "Cell2 Discharging" 4 "Cell3 Discharging" 8 "Cell4 Discharging" 16 "Cell5 Discharging" 134217728 "Cell28 Discharging" 268435456 "Cell29 Discharging" ;
VAL_ 2400448068 BalDchg_PosCellHigh_04 0 "No Discharging" 1 "Cell1 Discharging" 2 "Cell2 Discharging" 4 "Cell3 Discharging" 8 "Cell4 Discharging" 16 "Cell5 Discharging" 134217728 "Cell28 Discharging" 268435456 "Cell29 Discharging" ;
VAL_ 2400448069 CSC_B_No_05 1 "CSC 1" 2 "CSC 2" 3 "CSC 3" 4 "CSC 4" 5 "CSC 5" 6 "CSC 6" 31 "CSC31" ;
VAL_ 2400448069 BalDchg_PosCellLow_05 0 "No Discharging" 1 "Cell1 Discharging" 2 "Cell2 Discharging" 4 "Cell3 Discharging" 8 "Cell4 Discharging" 16 "Cell5 Discharging" 134217728 "Cell28 Discharging" 268435456 "Cell29 Discharging" ;
VAL_ 2400448069 BalDchg_PosCellHigh_05 0 "No Discharging" 1 "Cell1 Discharging" 2 "Cell2 Discharging" 4 "Cell3 Discharging" 8 "Cell4 Discharging" 16 "Cell5 Discharging" 134217728 "Cell28 Discharging" 268435456 "Cell29 Discharging" ;
VAL_ 2400448070 CSC_B_No_06 1 "CSC 1" 2 "CSC 2" 3 "CSC 3" 4 "CSC 4" 5 "CSC 5" 6 "CSC 6" 31 "CSC31" ;
VAL_ 2400448070 BalDchg_PosCellLow_06 0 "No Discharging" 1 "Cell1 Discharging" 2 "Cell2 Discharging" 4 "Cell3 Discharging" 8 "Cell4 Discharging" 16 "Cell5 Discharging" 134217728 "Cell28 Discharging" 268435456 "Cell29 Discharging" ;
VAL_ 2400448070 BalDchg_PosCellHigh_06 0 "No Discharging" 1 "Cell1 Discharging" 2 "Cell2 Discharging" 4 "Cell3 Discharging" 8 "Cell4 Discharging" 16 "Cell5 Discharging" 134217728 "Cell28 Discharging" 268435456 "Cell29 Discharging" ;
VAL_ 2400448071 CSC_B_No_07 1 "CSC 1" 2 "CSC 2" 3 "CSC 3" 4 "CSC 4" 5 "CSC 5" 6 "CSC 6" 31 "CSC31" ;
VAL_ 2400448071 BalDchg_PosCellLow_07 0 "No Discharging" 1 "Cell1 Discharging" 2 "Cell2 Discharging" 4 "Cell3 Discharging" 8 "Cell4 Discharging" 16 "Cell5 Discharging" 134217728 "Cell28 Discharging" 268435456 "Cell29 Discharging" ;
VAL_ 2400448071 BalDchg_PosCellHigh_07 0 "No Discharging" 1 "Cell1 Discharging" 2 "Cell2 Discharging" 4 "Cell3 Discharging" 8 "Cell4 Discharging" 16 "Cell5 Discharging" 134217728 "Cell28 Discharging" 268435456 "Cell29 Discharging" ;
VAL_ 2400448072 CSC_B_No_08 1 "CSC 1" 2 "CSC 2" 3 "CSC 3" 4 "CSC 4" 5 "CSC 5" 6 "CSC 6" 31 "CSC31" ;
VAL_ 2400448072 BalDchg_PosCellLow_08 0 "No Discharging" 1 "Cell1 Discharging" 2 "Cell2 Discharging" 4 "Cell3 Discharging" 8 "Cell4 Discharging" 16 "Cell5 Discharging" 134217728 "Cell28 Discharging" 268435456 "Cell29 Discharging" ;
VAL_ 2400448072 BalDchg_PosCellHigh_08 0 "No Discharging" 1 "Cell1 Discharging" 2 "Cell2 Discharging" 4 "Cell3 Discharging" 8 "Cell4 Discharging" 16 "Cell5 Discharging" 134217728 "Cell28 Discharging" 268435456 "Cell29 Discharging" ;
VAL_ 2400448073 CSC_B_No_09 1 "CSC 1" 2 "CSC 2" 3 "CSC 3" 4 "CSC 4" 5 "CSC 5" 6 "CSC 6" 31 "CSC31" ;
VAL_ 2400448073 BalDchg_PosCellLow_09 0 "No Discharging" 1 "Cell1 Discharging" 2 "Cell2 Discharging" 4 "Cell3 Discharging" 8 "Cell4 Discharging" 16 "Cell5 Discharging" 134217728 "Cell28 Discharging" 268435456 "Cell29 Discharging" ;
VAL_ 2400448073 BalDchg_PosCellHigh_09 0 "No Discharging" 1 "Cell1 Discharging" 2 "Cell2 Discharging" 4 "Cell3 Discharging" 8 "Cell4 Discharging" 16 "Cell5 Discharging" 134217728 "Cell28 Discharging" 268435456 "Cell29 Discharging" ;
VAL_ 2400448074 CSC_B_No_10 1 "CSC 1" 2 "CSC 2" 3 "CSC 3" 4 "CSC 4" 5 "CSC 5" 6 "CSC 6" 31 "CSC31" ;
VAL_ 2400448074 BalDchg_PosCellLow_10 0 "No Discharging" 1 "Cell1 Discharging" 2 "Cell2 Discharging" 4 "Cell3 Discharging" 8 "Cell4 Discharging" 16 "Cell5 Discharging" 134217728 "Cell28 Discharging" 268435456 "Cell29 Discharging" ;
VAL_ 2400448074 BalDchg_PosCellHigh_10 0 "No Discharging" 1 "Cell1 Discharging" 2 "Cell2 Discharging" 4 "Cell3 Discharging" 8 "Cell4 Discharging" 16 "Cell5 Discharging" 134217728 "Cell28 Discharging" 268435456 "Cell29 Discharging" ;
VAL_ 2400448075 CSC_B_No_11 1 "CSC 1" 2 "CSC 2" 3 "CSC 3" 4 "CSC 4" 5 "CSC 5" 6 "CSC 6" 31 "CSC31" ;
VAL_ 2400448075 BalDchg_PosCellLow_11 0 "No Discharging" 1 "Cell1 Discharging" 2 "Cell2 Discharging" 4 "Cell3 Discharging" 8 "Cell4 Discharging" 16 "Cell5 Discharging" 134217728 "Cell28 Discharging" 268435456 "Cell29 Discharging" ;
VAL_ 2400448075 BalDchg_PosCellHigh_11 0 "No Discharging" 1 "Cell1 Discharging" 2 "Cell2 Discharging" 4 "Cell3 Discharging" 8 "Cell4 Discharging" 16 "Cell5 Discharging" 134217728 "Cell28 Discharging" 268435456 "Cell29 Discharging" ;
VAL_ 2400448076 CSC_B_No_12 1 "CSC 1" 2 "CSC 2" 3 "CSC 3" 4 "CSC 4" 5 "CSC 5" 6 "CSC 6" 31 "CSC31" ;
VAL_ 2400448076 BalDchg_PosCellLow_12 0 "No Discharging" 1 "Cell1 Discharging" 2 "Cell2 Discharging" 4 "Cell3 Discharging" 8 "Cell4 Discharging" 16 "Cell5 Discharging" 134217728 "Cell28 Discharging" 268435456 "Cell29 Discharging" ;
VAL_ 2400448076 BalDchg_PosCellHigh_12 0 "No Discharging" 1 "Cell1 Discharging" 2 "Cell2 Discharging" 4 "Cell3 Discharging" 8 "Cell4 Discharging" 16 "Cell5 Discharging" 134217728 "Cell28 Discharging" 268435456 "Cell29 Discharging" ;
VAL_ 2400448077 CSC_B_No_13 1 "CSC 1" 2 "CSC 2" 3 "CSC 3" 4 "CSC 4" 5 "CSC 5" 6 "CSC 6" 31 "CSC31" ;
VAL_ 2400448077 BalDchg_PosCellLow_13 0 "No Discharging" 1 "Cell1 Discharging" 2 "Cell2 Discharging" 4 "Cell3 Discharging" 8 "Cell4 Discharging" 16 "Cell5 Discharging" 134217728 "Cell28 Discharging" 268435456 "Cell29 Discharging" ;
VAL_ 2400448077 BalDchg_PosCellHigh_13 0 "No Discharging" 1 "Cell1 Discharging" 2 "Cell2 Discharging" 4 "Cell3 Discharging" 8 "Cell4 Discharging" 16 "Cell5 Discharging" 134217728 "Cell28 Discharging" 268435456 "Cell29 Discharging" ;
VAL_ 2400448078 CSC_B_No_14 1 "CSC 1" 2 "CSC 2" 3 "CSC 3" 4 "CSC 4" 5 "CSC 5" 6 "CSC 6" 31 "CSC31" ;
VAL_ 2400448078 BalDchg_PosCellLow_14 0 "No Discharging" 1 "Cell1 Discharging" 2 "Cell2 Discharging" 4 "Cell3 Discharging" 8 "Cell4 Discharging" 16 "Cell5 Discharging" 134217728 "Cell28 Discharging" 268435456 "Cell29 Discharging" ;
VAL_ 2400448078 BalDchg_PosCellHigh_14 0 "No Discharging" 1 "Cell1 Discharging" 2 "Cell2 Discharging" 4 "Cell3 Discharging" 8 "Cell4 Discharging" 16 "Cell5 Discharging" 134217728 "Cell28 Discharging" 268435456 "Cell29 Discharging" ;
VAL_ 2400448079 CSC_B_No_15 1 "CSC 1" 2 "CSC 2" 3 "CSC 3" 4 "CSC 4" 5 "CSC 5" 6 "CSC 6" 31 "CSC31" ;
VAL_ 2400448079 BalDchg_PosCellLow_15 0 "No Discharging" 1 "Cell1 Discharging" 2 "Cell2 Discharging" 4 "Cell3 Discharging" 8 "Cell4 Discharging" 16 "Cell5 Discharging" 134217728 "Cell28 Discharging" 268435456 "Cell29 Discharging" ;
VAL_ 2400448079 BalDchg_PosCellHigh_15 0 "No Discharging" 1 "Cell1 Discharging" 2 "Cell2 Discharging" 4 "Cell3 Discharging" 8 "Cell4 Discharging" 16 "Cell5 Discharging" 134217728 "Cell28 Discharging" 268435456 "Cell29 Discharging" ;
VAL_ 2400448080 CSC_B_No_16 1 "CSC 1" 2 "CSC 2" 3 "CSC 3" 4 "CSC 4" 5 "CSC 5" 6 "CSC 6" 31 "CSC31" ;
VAL_ 2400448080 BalDchg_PosCellLow_16 0 "No Discharging" 1 "Cell1 Discharging" 2 "Cell2 Discharging" 4 "Cell3 Discharging" 8 "Cell4 Discharging" 16 "Cell5 Discharging" 134217728 "Cell28 Discharging" 268435456 "Cell29 Discharging" ;
VAL_ 2400448080 BalDchg_PosCellHigh_16 0 "No Discharging" 1 "Cell1 Discharging" 2 "Cell2 Discharging" 4 "Cell3 Discharging" 8 "Cell4 Discharging" 16 "Cell5 Discharging" 134217728 "Cell28 Discharging" 268435456 "Cell29 Discharging" ;
VAL_ 2400448081 CSC_B_No_17 1 "CSC 1" 2 "CSC 2" 3 "CSC 3" 4 "CSC 4" 5 "CSC 5" 6 "CSC 6" 31 "CSC31" ;
VAL_ 2400448081 BalDchg_PosCellLow_17 0 "No Discharging" 1 "Cell1 Discharging" 2 "Cell2 Discharging" 4 "Cell3 Discharging" 8 "Cell4 Discharging" 16 "Cell5 Discharging" 134217728 "Cell28 Discharging" 268435456 "Cell29 Discharging" ;
VAL_ 2400448081 BalDchg_PosCellHigh_17 0 "No Discharging" 1 "Cell1 Discharging" 2 "Cell2 Discharging" 4 "Cell3 Discharging" 8 "Cell4 Discharging" 16 "Cell5 Discharging" 134217728 "Cell28 Discharging" 268435456 "Cell29 Discharging" ;
VAL_ 2400448082 CSC_B_No_18 1 "CSC 1" 2 "CSC 2" 3 "CSC 3" 4 "CSC 4" 5 "CSC 5" 6 "CSC 6" 31 "CSC31" ;
VAL_ 2400448082 BalDchg_PosCellLow_18 0 "No Discharging" 1 "Cell1 Discharging" 2 "Cell2 Discharging" 4 "Cell3 Discharging" 8 "Cell4 Discharging" 16 "Cell5 Discharging" 134217728 "Cell28 Discharging" 268435456 "Cell29 Discharging" ;
VAL_ 2400448082 BalDchg_PosCellHigh_18 0 "No Discharging" 1 "Cell1 Discharging" 2 "Cell2 Discharging" 4 "Cell3 Discharging" 8 "Cell4 Discharging" 16 "Cell5 Discharging" 134217728 "Cell28 Discharging" 268435456 "Cell29 Discharging" ;
VAL_ 2400448083 CSC_B_No_19 1 "CSC 1" 2 "CSC 2" 3 "CSC 3" 4 "CSC 4" 5 "CSC 5" 6 "CSC 6" 31 "CSC31" ;
VAL_ 2400448083 BalDchg_PosCellLow_19 0 "No Discharging" 1 "Cell1 Discharging" 2 "Cell2 Discharging" 4 "Cell3 Discharging" 8 "Cell4 Discharging" 16 "Cell5 Discharging" 134217728 "Cell28 Discharging" 268435456 "Cell29 Discharging" ;
VAL_ 2400448083 BalDchg_PosCellHigh_19 0 "No Discharging" 1 "Cell1 Discharging" 2 "Cell2 Discharging" 4 "Cell3 Discharging" 8 "Cell4 Discharging" 16 "Cell5 Discharging" 134217728 "Cell28 Discharging" 268435456 "Cell29 Discharging" ;
VAL_ 2400448084 CSC_B_No_20 1 "CSC 1" 2 "CSC 2" 3 "CSC 3" 4 "CSC 4" 5 "CSC 5" 6 "CSC 6" 31 "CSC31" ;
VAL_ 2400448084 BalDchg_PosCellLow_20 0 "No Discharging" 1 "Cell1 Discharging" 2 "Cell2 Discharging" 4 "Cell3 Discharging" 8 "Cell4 Discharging" 16 "Cell5 Discharging" 134217728 "Cell28 Discharging" 268435456 "Cell29 Discharging" ;
VAL_ 2400448084 BalDchg_PosCellHigh_20 0 "No Discharging" 1 "Cell1 Discharging" 2 "Cell2 Discharging" 4 "Cell3 Discharging" 8 "Cell4 Discharging" 16 "Cell5 Discharging" 134217728 "Cell28 Discharging" 268435456 "Cell29 Discharging" ;
VAL_ 2400448085 CSC_B_No_21 1 "CSC 1" 2 "CSC 2" 3 "CSC 3" 4 "CSC 4" 5 "CSC 5" 6 "CSC 6" 31 "CSC31" ;
VAL_ 2400448085 BalDchg_PosCellLow_21 0 "No Discharging" 1 "Cell1 Discharging" 2 "Cell2 Discharging" 4 "Cell3 Discharging" 8 "Cell4 Discharging" 16 "Cell5 Discharging" 134217728 "Cell28 Discharging" 268435456 "Cell29 Discharging" ;
VAL_ 2400448085 BalDchg_PosCellHigh_21 0 "No Discharging" 1 "Cell1 Discharging" 2 "Cell2 Discharging" 4 "Cell3 Discharging" 8 "Cell4 Discharging" 16 "Cell5 Discharging" 134217728 "Cell28 Discharging" 268435456 "Cell29 Discharging" ;
VAL_ 2400448086 CSC_B_No_22 1 "CSC 1" 2 "CSC 2" 3 "CSC 3" 4 "CSC 4" 5 "CSC 5" 6 "CSC 6" 31 "CSC31" ;
VAL_ 2400448086 BalDchg_PosCellLow_22 0 "No Discharging" 1 "Cell1 Discharging" 2 "Cell2 Discharging" 4 "Cell3 Discharging" 8 "Cell4 Discharging" 16 "Cell5 Discharging" 134217728 "Cell28 Discharging" 268435456 "Cell29 Discharging" ;
VAL_ 2400448086 BalDchg_PosCellHigh_22 0 "No Discharging" 1 "Cell1 Discharging" 2 "Cell2 Discharging" 4 "Cell3 Discharging" 8 "Cell4 Discharging" 16 "Cell5 Discharging" 134217728 "Cell28 Discharging" 268435456 "Cell29 Discharging" ;
VAL_ 2400448087 CSC_B_No_23 1 "CSC 1" 2 "CSC 2" 3 "CSC 3" 4 "CSC 4" 5 "CSC 5" 6 "CSC 6" 31 "CSC31" ;
VAL_ 2400448087 BalDchg_PosCellLow_23 0 "No Discharging" 1 "Cell1 Discharging" 2 "Cell2 Discharging" 4 "Cell3 Discharging" 8 "Cell4 Discharging" 16 "Cell5 Discharging" 134217728 "Cell28 Discharging" 268435456 "Cell29 Discharging" ;
VAL_ 2400448087 BalDchg_PosCellHigh_23 0 "No Discharging" 1 "Cell1 Discharging" 2 "Cell2 Discharging" 4 "Cell3 Discharging" 8 "Cell4 Discharging" 16 "Cell5 Discharging" 134217728 "Cell28 Discharging" 268435456 "Cell29 Discharging" ;
VAL_ 2400448088 CSC_B_No_24 1 "CSC 1" 2 "CSC 2" 3 "CSC 3" 4 "CSC 4" 5 "CSC 5" 6 "CSC 6" 31 "CSC31" ;
VAL_ 2400448088 BalDchg_PosCellLow_24 0 "No Discharging" 1 "Cell1 Discharging" 2 "Cell2 Discharging" 4 "Cell3 Discharging" 8 "Cell4 Discharging" 16 "Cell5 Discharging" 134217728 "Cell28 Discharging" 268435456 "Cell29 Discharging" ;
VAL_ 2400448088 BalDchg_PosCellHigh_24 0 "No Discharging" 1 "Cell1 Discharging" 2 "Cell2 Discharging" 4 "Cell3 Discharging" 8 "Cell4 Discharging" 16 "Cell5 Discharging" 134217728 "Cell28 Discharging" 268435456 "Cell29 Discharging" ;
VAL_ 2400448089 CSC_B_No_25 1 "CSC 1" 2 "CSC 2" 3 "CSC 3" 4 "CSC 4" 5 "CSC 5" 6 "CSC 6" 31 "CSC31" ;
VAL_ 2400448089 BalDchg_PosCellLow_25 0 "No Discharging" 1 "Cell1 Discharging" 2 "Cell2 Discharging" 4 "Cell3 Discharging" 8 "Cell4 Discharging" 16 "Cell5 Discharging" 134217728 "Cell28 Discharging" 268435456 "Cell29 Discharging" ;
VAL_ 2400448089 BalDchg_PosCellHigh_25 0 "No Discharging" 1 "Cell1 Discharging" 2 "Cell2 Discharging" 4 "Cell3 Discharging" 8 "Cell4 Discharging" 16 "Cell5 Discharging" 134217728 "Cell28 Discharging" 268435456 "Cell29 Discharging" ;
VAL_ 2400448090 CSC_B_No_26 1 "CSC 1" 2 "CSC 2" 3 "CSC 3" 4 "CSC 4" 5 "CSC 5" 6 "CSC 6" 31 "CSC31" ;
VAL_ 2400448090 BalDchg_PosCellLow_26 0 "No Discharging" 1 "Cell1 Discharging" 2 "Cell2 Discharging" 4 "Cell3 Discharging" 8 "Cell4 Discharging" 16 "Cell5 Discharging" 134217728 "Cell28 Discharging" 268435456 "Cell29 Discharging" ;
VAL_ 2400448090 BalDchg_PosCellHigh_26 0 "No Discharging" 1 "Cell1 Discharging" 2 "Cell2 Discharging" 4 "Cell3 Discharging" 8 "Cell4 Discharging" 16 "Cell5 Discharging" 134217728 "Cell28 Discharging" 268435456 "Cell29 Discharging" ;
VAL_ 2400448091 CSC_B_No_27 1 "CSC 1" 2 "CSC 2" 3 "CSC 3" 4 "CSC 4" 5 "CSC 5" 6 "CSC 6" 31 "CSC31" ;
VAL_ 2400448091 BalDchg_PosCellLow_27 0 "No Discharging" 1 "Cell1 Discharging" 2 "Cell2 Discharging" 4 "Cell3 Discharging" 8 "Cell4 Discharging" 16 "Cell5 Discharging" 134217728 "Cell28 Discharging" 268435456 "Cell29 Discharging" ;
VAL_ 2400448091 BalDchg_PosCellHigh_27 0 "No Discharging" 1 "Cell1 Discharging" 2 "Cell2 Discharging" 4 "Cell3 Discharging" 8 "Cell4 Discharging" 16 "Cell5 Discharging" 134217728 "Cell28 Discharging" 268435456 "Cell29 Discharging" ;
VAL_ 2400448092 CSC_B_No_28 1 "CSC 1" 2 "CSC 2" 3 "CSC 3" 4 "CSC 4" 5 "CSC 5" 6 "CSC 6" 31 "CSC31" ;
VAL_ 2400448092 BalDchg_PosCellLow_28 0 "No Discharging" 1 "Cell1 Discharging" 2 "Cell2 Discharging" 4 "Cell3 Discharging" 8 "Cell4 Discharging" 16 "Cell5 Discharging" 134217728 "Cell28 Discharging" 268435456 "Cell29 Discharging" ;
VAL_ 2400448092 BalDchg_PosCellHigh_28 0 "No Discharging" 1 "Cell1 Discharging" 2 "Cell2 Discharging" 4 "Cell3 Discharging" 8 "Cell4 Discharging" 16 "Cell5 Discharging" 134217728 "Cell28 Discharging" 268435456 "Cell29 Discharging" ;
VAL_ 2400448093 CSC_B_No_29 1 "CSC 1" 2 "CSC 2" 3 "CSC 3" 4 "CSC 4" 5 "CSC 5" 6 "CSC 6" 31 "CSC31" ;
VAL_ 2400448093 BalDchg_PosCellLow_29 0 "No Discharging" 1 "Cell1 Discharging" 2 "Cell2 Discharging" 4 "Cell3 Discharging" 8 "Cell4 Discharging" 16 "Cell5 Discharging" 134217728 "Cell28 Discharging" 268435456 "Cell29 Discharging" ;
VAL_ 2400448093 BalDchg_PosCellHigh_29 0 "No Discharging" 1 "Cell1 Discharging" 2 "Cell2 Discharging" 4 "Cell3 Discharging" 8 "Cell4 Discharging" 16 "Cell5 Discharging" 134217728 "Cell28 Discharging" 268435456 "Cell29 Discharging" ;
VAL_ 2400448094 CSC_B_No_30 1 "CSC 1" 2 "CSC 2" 3 "CSC 3" 4 "CSC 4" 5 "CSC 5" 6 "CSC 6" 31 "CSC31" ;
VAL_ 2400448094 BalDchg_PosCellLow_30 0 "No Discharging" 1 "Cell1 Discharging" 2 "Cell2 Discharging" 4 "Cell3 Discharging" 8 "Cell4 Discharging" 16 "Cell5 Discharging" 134217728 "Cell28 Discharging" 268435456 "Cell29 Discharging" ;
VAL_ 2400448094 BalDchg_PosCellHigh_30 0 "No Discharging" 1 "Cell1 Discharging" 2 "Cell2 Discharging" 4 "Cell3 Discharging" 8 "Cell4 Discharging" 16 "Cell5 Discharging" 134217728 "Cell28 Discharging" 268435456 "Cell29 Discharging" ;
VAL_ 2400448095 CSC_B_No_31 1 "CSC 1" 2 "CSC 2" 3 "CSC 3" 4 "CSC 4" 5 "CSC 5" 6 "CSC 6" 31 "CSC31" ;
VAL_ 2400448095 BalDchg_PosCellLow_31 0 "No Discharging" 1 "Cell1 Discharging" 2 "Cell2 Discharging" 4 "Cell3 Discharging" 8 "Cell4 Discharging" 16 "Cell5 Discharging" 134217728 "Cell28 Discharging" 268435456 "Cell29 Discharging" ;
VAL_ 2400448095 BalDchg_PosCellHigh_31 0 "No Discharging" 1 "Cell1 Discharging" 2 "Cell2 Discharging" 4 "Cell3 Discharging" 8 "Cell4 Discharging" 16 "Cell5 Discharging" 134217728 "Cell28 Discharging" 268435456 "Cell29 Discharging" ;
VAL_ 2400448096 CSC_B_No_32 1 "CSC 1" 2 "CSC 2" 3 "CSC 3" 4 "CSC 4" 5 "CSC 5" 6 "CSC 6" 31 "CSC31" ;
VAL_ 2400448096 BalDchg_PosCellLow_32 0 "No Discharging" 1 "Cell1 Discharging" 2 "Cell2 Discharging" 4 "Cell3 Discharging" 8 "Cell4 Discharging" 16 "Cell5 Discharging" 134217728 "Cell28 Discharging" 268435456 "Cell29 Discharging" ;
VAL_ 2400448096 BalDchg_PosCellHigh_32 0 "No Discharging" 1 "Cell1 Discharging" 2 "Cell2 Discharging" 4 "Cell3 Discharging" 8 "Cell4 Discharging" 16 "Cell5 Discharging" 134217728 "Cell28 Discharging" 268435456 "Cell29 Discharging" ;
VAL_ 2400448097 CSC_B_No_33 1 "CSC 1" 2 "CSC 2" 3 "CSC 3" 4 "CSC 4" 5 "CSC 5" 6 "CSC 6" 31 "CSC31" ;
VAL_ 2400448097 BalDchg_PosCellLow_33 0 "No Discharging" 1 "Cell1 Discharging" 2 "Cell2 Discharging" 4 "Cell3 Discharging" 8 "Cell4 Discharging" 16 "Cell5 Discharging" 134217728 "Cell28 Discharging" 268435456 "Cell29 Discharging" ;
VAL_ 2400448097 BalDchg_PosCellHigh_33 0 "No Discharging" 1 "Cell1 Discharging" 2 "Cell2 Discharging" 4 "Cell3 Discharging" 8 "Cell4 Discharging" 16 "Cell5 Discharging" 134217728 "Cell28 Discharging" 268435456 "Cell29 Discharging" ;
VAL_ 2400448098 CSC_B_No_34 1 "CSC 1" 2 "CSC 2" 3 "CSC 3" 4 "CSC 4" 5 "CSC 5" 6 "CSC 6" 31 "CSC31" ;
VAL_ 2400448098 BalDchg_PosCellLow_34 0 "No Discharging" 1 "Cell1 Discharging" 2 "Cell2 Discharging" 4 "Cell3 Discharging" 8 "Cell4 Discharging" 16 "Cell5 Discharging" 134217728 "Cell28 Discharging" 268435456 "Cell29 Discharging" ;
VAL_ 2400448098 BalDchg_PosCellHigh_34 0 "No Discharging" 1 "Cell1 Discharging" 2 "Cell2 Discharging" 4 "Cell3 Discharging" 8 "Cell4 Discharging" 16 "Cell5 Discharging" 134217728 "Cell28 Discharging" 268435456 "Cell29 Discharging" ;
VAL_ 2400448099 CSC_B_No_35 1 "CSC 1" 2 "CSC 2" 3 "CSC 3" 4 "CSC 4" 5 "CSC 5" 6 "CSC 6" 31 "CSC31" ;
VAL_ 2400448099 BalDchg_PosCellLow_35 0 "No Discharging" 1 "Cell1 Discharging" 2 "Cell2 Discharging" 4 "Cell3 Discharging" 8 "Cell4 Discharging" 16 "Cell5 Discharging" 134217728 "Cell28 Discharging" 268435456 "Cell29 Discharging" ;
VAL_ 2400448099 BalDchg_PosCellHigh_35 0 "No Discharging" 1 "Cell1 Discharging" 2 "Cell2 Discharging" 4 "Cell3 Discharging" 8 "Cell4 Discharging" 16 "Cell5 Discharging" 134217728 "Cell28 Discharging" 268435456 "Cell29 Discharging" ;
VAL_ 2400448100 CSC_B_No_36 1 "CSC 1" 2 "CSC 2" 3 "CSC 3" 4 "CSC 4" 5 "CSC 5" 6 "CSC 6" 31 "CSC31" ;
VAL_ 2400448100 BalDchg_PosCellLow_36 0 "No Discharging" 1 "Cell1 Discharging" 2 "Cell2 Discharging" 4 "Cell3 Discharging" 8 "Cell4 Discharging" 16 "Cell5 Discharging" 134217728 "Cell28 Discharging" 268435456 "Cell29 Discharging" ;
VAL_ 2400448100 BalDchg_PosCellHigh_36 0 "No Discharging" 1 "Cell1 Discharging" 2 "Cell2 Discharging" 4 "Cell3 Discharging" 8 "Cell4 Discharging" 16 "Cell5 Discharging" 134217728 "Cell28 Discharging" 268435456 "Cell29 Discharging" ;
VAL_ 2400448101 CSC_B_No_37 1 "CSC 1" 2 "CSC 2" 3 "CSC 3" 4 "CSC 4" 5 "CSC 5" 6 "CSC 6" 31 "CSC31" ;
VAL_ 2400448101 BalDchg_PosCellLow_37 0 "No Discharging" 1 "Cell1 Discharging" 2 "Cell2 Discharging" 4 "Cell3 Discharging" 8 "Cell4 Discharging" 16 "Cell5 Discharging" 134217728 "Cell28 Discharging" 268435456 "Cell29 Discharging" ;
VAL_ 2400448101 BalDchg_PosCellHigh_37 0 "No Discharging" 1 "Cell1 Discharging" 2 "Cell2 Discharging" 4 "Cell3 Discharging" 8 "Cell4 Discharging" 16 "Cell5 Discharging" 134217728 "Cell28 Discharging" 268435456 "Cell29 Discharging" ;
VAL_ 2400448102 CSC_B_No_38 1 "CSC 1" 2 "CSC 2" 3 "CSC 3" 4 "CSC 4" 5 "CSC 5" 6 "CSC 6" 31 "CSC31" ;
VAL_ 2400448102 BalDchg_PosCellLow_38 0 "No Discharging" 1 "Cell1 Discharging" 2 "Cell2 Discharging" 4 "Cell3 Discharging" 8 "Cell4 Discharging" 16 "Cell5 Discharging" 134217728 "Cell28 Discharging" 268435456 "Cell29 Discharging" ;
VAL_ 2400448102 BalDchg_PosCellHigh_38 0 "No Discharging" 1 "Cell1 Discharging" 2 "Cell2 Discharging" 4 "Cell3 Discharging" 8 "Cell4 Discharging" 16 "Cell5 Discharging" 134217728 "Cell28 Discharging" 268435456 "Cell29 Discharging" ;
VAL_ 2400448103 CSC_B_No_39 1 "CSC 1" 2 "CSC 2" 3 "CSC 3" 4 "CSC 4" 5 "CSC 5" 6 "CSC 6" 31 "CSC31" ;
VAL_ 2400448103 BalDchg_PosCellLow_39 0 "No Discharging" 1 "Cell1 Discharging" 2 "Cell2 Discharging" 4 "Cell3 Discharging" 8 "Cell4 Discharging" 16 "Cell5 Discharging" 134217728 "Cell28 Discharging" 268435456 "Cell29 Discharging" ;
VAL_ 2400448103 BalDchg_PosCellHigh_39 0 "No Discharging" 1 "Cell1 Discharging" 2 "Cell2 Discharging" 4 "Cell3 Discharging" 8 "Cell4 Discharging" 16 "Cell5 Discharging" 134217728 "Cell28 Discharging" 268435456 "Cell29 Discharging" ;
VAL_ 2400448104 CSC_B_No_40 1 "CSC 1" 2 "CSC 2" 3 "CSC 3" 4 "CSC 4" 5 "CSC 5" 6 "CSC 6" 31 "CSC31" ;
VAL_ 2400448104 BalDchg_PosCellLow_40 0 "No Discharging" 1 "Cell1 Discharging" 2 "Cell2 Discharging" 4 "Cell3 Discharging" 8 "Cell4 Discharging" 16 "Cell5 Discharging" 134217728 "Cell28 Discharging" 268435456 "Cell29 Discharging" ;
VAL_ 2400448104 BalDchg_PosCellHigh_40 0 "No Discharging" 1 "Cell1 Discharging" 2 "Cell2 Discharging" 4 "Cell3 Discharging" 8 "Cell4 Discharging" 16 "Cell5 Discharging" 134217728 "Cell28 Discharging" 268435456 "Cell29 Discharging" ;
VAL_ 2400448105 CSC_B_No_41 1 "CSC 1" 2 "CSC 2" 3 "CSC 3" 4 "CSC 4" 5 "CSC 5" 6 "CSC 6" 31 "CSC31" ;
VAL_ 2400448105 BalDchg_PosCellLow_41 0 "No Discharging" 1 "Cell1 Discharging" 2 "Cell2 Discharging" 4 "Cell3 Discharging" 8 "Cell4 Discharging" 16 "Cell5 Discharging" 134217728 "Cell28 Discharging" 268435456 "Cell29 Discharging" ;
VAL_ 2400448105 BalDchg_PosCellHigh_41 0 "No Discharging" 1 "Cell1 Discharging" 2 "Cell2 Discharging" 4 "Cell3 Discharging" 8 "Cell4 Discharging" 16 "Cell5 Discharging" 134217728 "Cell28 Discharging" 268435456 "Cell29 Discharging" ;
VAL_ 2400448106 CSC_B_No_42 1 "CSC 1" 2 "CSC 2" 3 "CSC 3" 4 "CSC 4" 5 "CSC 5" 6 "CSC 6" 31 "CSC31" ;
VAL_ 2400448106 BalDchg_PosCellLow_42 0 "No Discharging" 1 "Cell1 Discharging" 2 "Cell2 Discharging" 4 "Cell3 Discharging" 8 "Cell4 Discharging" 16 "Cell5 Discharging" 134217728 "Cell28 Discharging" 268435456 "Cell29 Discharging" ;
VAL_ 2400448106 BalDchg_PosCellHigh_42 0 "No Discharging" 1 "Cell1 Discharging" 2 "Cell2 Discharging" 4 "Cell3 Discharging" 8 "Cell4 Discharging" 16 "Cell5 Discharging" 134217728 "Cell28 Discharging" 268435456 "Cell29 Discharging" ;
VAL_ 2400448107 CSC_B_No_43 1 "CSC 1" 2 "CSC 2" 3 "CSC 3" 4 "CSC 4" 5 "CSC 5" 6 "CSC 6" 31 "CSC31" ;
VAL_ 2400448107 BalDchg_PosCellLow_43 0 "No Discharging" 1 "Cell1 Discharging" 2 "Cell2 Discharging" 4 "Cell3 Discharging" 8 "Cell4 Discharging" 16 "Cell5 Discharging" 134217728 "Cell28 Discharging" 268435456 "Cell29 Discharging" ;
VAL_ 2400448107 BalDchg_PosCellHigh_43 0 "No Discharging" 1 "Cell1 Discharging" 2 "Cell2 Discharging" 4 "Cell3 Discharging" 8 "Cell4 Discharging" 16 "Cell5 Discharging" 134217728 "Cell28 Discharging" 268435456 "Cell29 Discharging" ;
VAL_ 2400448108 CSC_B_No_44 1 "CSC 1" 2 "CSC 2" 3 "CSC 3" 4 "CSC 4" 5 "CSC 5" 6 "CSC 6" 31 "CSC31" ;
VAL_ 2400448108 BalDchg_PosCellLow_44 0 "No Discharging" 1 "Cell1 Discharging" 2 "Cell2 Discharging" 4 "Cell3 Discharging" 8 "Cell4 Discharging" 16 "Cell5 Discharging" 134217728 "Cell28 Discharging" 268435456 "Cell29 Discharging" ;
VAL_ 2400448108 BalDchg_PosCellHigh_44 0 "No Discharging" 1 "Cell1 Discharging" 2 "Cell2 Discharging" 4 "Cell3 Discharging" 8 "Cell4 Discharging" 16 "Cell5 Discharging" 134217728 "Cell28 Discharging" 268435456 "Cell29 Discharging" ;
VAL_ 2400448109 CSC_B_No_45 1 "CSC 1" 2 "CSC 2" 3 "CSC 3" 4 "CSC 4" 5 "CSC 5" 6 "CSC 6" 31 "CSC31" ;
VAL_ 2400448109 BalDchg_PosCellLow_45 0 "No Discharging" 1 "Cell1 Discharging" 2 "Cell2 Discharging" 4 "Cell3 Discharging" 8 "Cell4 Discharging" 16 "Cell5 Discharging" 134217728 "Cell28 Discharging" 268435456 "Cell29 Discharging" ;
VAL_ 2400448109 BalDchg_PosCellHigh_45 0 "No Discharging" 1 "Cell1 Discharging" 2 "Cell2 Discharging" 4 "Cell3 Discharging" 8 "Cell4 Discharging" 16 "Cell5 Discharging" 134217728 "Cell28 Discharging" 268435456 "Cell29 Discharging" ;
VAL_ 2400448110 CSC_B_No_46 1 "CSC 1" 2 "CSC 2" 3 "CSC 3" 4 "CSC 4" 5 "CSC 5" 6 "CSC 6" 31 "CSC31" ;
VAL_ 2400448110 BalDchg_PosCellLow_46 0 "No Discharging" 1 "Cell1 Discharging" 2 "Cell2 Discharging" 4 "Cell3 Discharging" 8 "Cell4 Discharging" 16 "Cell5 Discharging" 134217728 "Cell28 Discharging" 268435456 "Cell29 Discharging" ;
VAL_ 2400448110 BalDchg_PosCellHigh_46 0 "No Discharging" 1 "Cell1 Discharging" 2 "Cell2 Discharging" 4 "Cell3 Discharging" 8 "Cell4 Discharging" 16 "Cell5 Discharging" 134217728 "Cell28 Discharging" 268435456 "Cell29 Discharging" ;
VAL_ 2400448111 CSC_B_No_47 1 "CSC 1" 2 "CSC 2" 3 "CSC 3" 4 "CSC 4" 5 "CSC 5" 6 "CSC 6" 31 "CSC31" ;
VAL_ 2400448111 BalDchg_PosCellLow_47 0 "No Discharging" 1 "Cell1 Discharging" 2 "Cell2 Discharging" 4 "Cell3 Discharging" 8 "Cell4 Discharging" 16 "Cell5 Discharging" 134217728 "Cell28 Discharging" 268435456 "Cell29 Discharging" ;
VAL_ 2400448111 BalDchg_PosCellHigh_47 0 "No Discharging" 1 "Cell1 Discharging" 2 "Cell2 Discharging" 4 "Cell3 Discharging" 8 "Cell4 Discharging" 16 "Cell5 Discharging" 134217728 "Cell28 Discharging" 268435456 "Cell29 Discharging" ;
VAL_ 2400448112 CSC_B_No_48 1 "CSC 1" 2 "CSC 2" 3 "CSC 3" 4 "CSC 4" 5 "CSC 5" 6 "CSC 6" 31 "CSC31" ;
VAL_ 2400448112 BalDchg_PosCellLow_48 0 "No Discharging" 1 "Cell1 Discharging" 2 "Cell2 Discharging" 4 "Cell3 Discharging" 8 "Cell4 Discharging" 16 "Cell5 Discharging" 134217728 "Cell28 Discharging" 268435456 "Cell29 Discharging" ;
VAL_ 2400448112 BalDchg_PosCellHigh_48 0 "No Discharging" 1 "Cell1 Discharging" 2 "Cell2 Discharging" 4 "Cell3 Discharging" 8 "Cell4 Discharging" 16 "Cell5 Discharging" 134217728 "Cell28 Discharging" 268435456 "Cell29 Discharging" ;
VAL_ 2400448113 CSC_B_No_49 1 "CSC 1" 2 "CSC 2" 3 "CSC 3" 4 "CSC 4" 5 "CSC 5" 6 "CSC 6" 31 "CSC31" ;
VAL_ 2400448113 BalDchg_PosCellLow_49 0 "No Discharging" 1 "Cell1 Discharging" 2 "Cell2 Discharging" 4 "Cell3 Discharging" 8 "Cell4 Discharging" 16 "Cell5 Discharging" 134217728 "Cell28 Discharging" 268435456 "Cell29 Discharging" ;
VAL_ 2400448113 BalDchg_PosCellHigh_49 0 "No Discharging" 1 "Cell1 Discharging" 2 "Cell2 Discharging" 4 "Cell3 Discharging" 8 "Cell4 Discharging" 16 "Cell5 Discharging" 134217728 "Cell28 Discharging" 268435456 "Cell29 Discharging" ;
VAL_ 2400448114 CSC_B_No_50 1 "CSC 1" 2 "CSC 2" 3 "CSC 3" 4 "CSC 4" 5 "CSC 5" 6 "CSC 6" 31 "CSC31" ;
VAL_ 2400448114 BalDchg_PosCellLow_50 0 "No Discharging" 1 "Cell1 Discharging" 2 "Cell2 Discharging" 4 "Cell3 Discharging" 8 "Cell4 Discharging" 16 "Cell5 Discharging" 134217728 "Cell28 Discharging" 268435456 "Cell29 Discharging" ;
VAL_ 2400448114 BalDchg_PosCellHigh_50 0 "No Discharging" 1 "Cell1 Discharging" 2 "Cell2 Discharging" 4 "Cell3 Discharging" 8 "Cell4 Discharging" 16 "Cell5 Discharging" 134217728 "Cell28 Discharging" 268435456 "Cell29 Discharging" ;
VAL_ 2400448115 CSC_B_No_51 1 "CSC 1" 2 "CSC 2" 3 "CSC 3" 4 "CSC 4" 5 "CSC 5" 6 "CSC 6" 31 "CSC31" ;
VAL_ 2400448115 BalDchg_PosCellLow_51 0 "No Discharging" 1 "Cell1 Discharging" 2 "Cell2 Discharging" 4 "Cell3 Discharging" 8 "Cell4 Discharging" 16 "Cell5 Discharging" 134217728 "Cell28 Discharging" 268435456 "Cell29 Discharging" ;
VAL_ 2400448115 BalDchg_PosCellHigh_51 0 "No Discharging" 1 "Cell1 Discharging" 2 "Cell2 Discharging" 4 "Cell3 Discharging" 8 "Cell4 Discharging" 16 "Cell5 Discharging" 134217728 "Cell28 Discharging" 268435456 "Cell29 Discharging" ;
VAL_ 2400448116 CSC_B_No_52 1 "CSC 1" 2 "CSC 2" 3 "CSC 3" 4 "CSC 4" 5 "CSC 5" 6 "CSC 6" 31 "CSC31" ;
VAL_ 2400448116 BalDchg_PosCellLow_52 0 "No Discharging" 1 "Cell1 Discharging" 2 "Cell2 Discharging" 4 "Cell3 Discharging" 8 "Cell4 Discharging" 16 "Cell5 Discharging" 134217728 "Cell28 Discharging" 268435456 "Cell29 Discharging" ;
VAL_ 2400448116 BalDchg_PosCellHigh_52 0 "No Discharging" 1 "Cell1 Discharging" 2 "Cell2 Discharging" 4 "Cell3 Discharging" 8 "Cell4 Discharging" 16 "Cell5 Discharging" 134217728 "Cell28 Discharging" 268435456 "Cell29 Discharging" ;
VAL_ 2400448117 CSC_B_No_53 1 "CSC 1" 2 "CSC 2" 3 "CSC 3" 4 "CSC 4" 5 "CSC 5" 6 "CSC 6" 31 "CSC31" ;
VAL_ 2400448117 BalDchg_PosCellLow_53 0 "No Discharging" 1 "Cell1 Discharging" 2 "Cell2 Discharging" 4 "Cell3 Discharging" 8 "Cell4 Discharging" 16 "Cell5 Discharging" 134217728 "Cell28 Discharging" 268435456 "Cell29 Discharging" ;
VAL_ 2400448117 BalDchg_PosCellHigh_53 0 "No Discharging" 1 "Cell1 Discharging" 2 "Cell2 Discharging" 4 "Cell3 Discharging" 8 "Cell4 Discharging" 16 "Cell5 Discharging" 134217728 "Cell28 Discharging" 268435456 "Cell29 Discharging" ;
VAL_ 2400448118 CSC_B_No_54 1 "CSC 1" 2 "CSC 2" 3 "CSC 3" 4 "CSC 4" 5 "CSC 5" 6 "CSC 6" 31 "CSC31" ;
VAL_ 2400448118 BalDchg_PosCellLow_54 0 "No Discharging" 1 "Cell1 Discharging" 2 "Cell2 Discharging" 4 "Cell3 Discharging" 8 "Cell4 Discharging" 16 "Cell5 Discharging" 134217728 "Cell28 Discharging" 268435456 "Cell29 Discharging" ;
VAL_ 2400448118 BalDchg_PosCellHigh_54 0 "No Discharging" 1 "Cell1 Discharging" 2 "Cell2 Discharging" 4 "Cell3 Discharging" 8 "Cell4 Discharging" 16 "Cell5 Discharging" 134217728 "Cell28 Discharging" 268435456 "Cell29 Discharging" ;
VAL_ 2400448119 CSC_B_No_55 1 "CSC 1" 2 "CSC 2" 3 "CSC 3" 4 "CSC 4" 5 "CSC 5" 6 "CSC 6" 31 "CSC31" ;
VAL_ 2400448119 BalDchg_PosCellLow_55 0 "No Discharging" 1 "Cell1 Discharging" 2 "Cell2 Discharging" 4 "Cell3 Discharging" 8 "Cell4 Discharging" 16 "Cell5 Discharging" 134217728 "Cell28 Discharging" 268435456 "Cell29 Discharging" ;
VAL_ 2400448119 BalDchg_PosCellHigh_55 0 "No Discharging" 1 "Cell1 Discharging" 2 "Cell2 Discharging" 4 "Cell3 Discharging" 8 "Cell4 Discharging" 16 "Cell5 Discharging" 134217728 "Cell28 Discharging" 268435456 "Cell29 Discharging" ;
VAL_ 2400448120 CSC_B_No_56 1 "CSC 1" 2 "CSC 2" 3 "CSC 3" 4 "CSC 4" 5 "CSC 5" 6 "CSC 6" 31 "CSC31" ;
VAL_ 2400448120 BalDchg_PosCellLow_56 0 "No Discharging" 1 "Cell1 Discharging" 2 "Cell2 Discharging" 4 "Cell3 Discharging" 8 "Cell4 Discharging" 16 "Cell5 Discharging" 134217728 "Cell28 Discharging" 268435456 "Cell29 Discharging" ;
VAL_ 2400448120 BalDchg_PosCellHigh_56 0 "No Discharging" 1 "Cell1 Discharging" 2 "Cell2 Discharging" 4 "Cell3 Discharging" 8 "Cell4 Discharging" 16 "Cell5 Discharging" 134217728 "Cell28 Discharging" 268435456 "Cell29 Discharging" ;
VAL_ 2400448121 CSC_B_No_57 1 "CSC 1" 2 "CSC 2" 3 "CSC 3" 4 "CSC 4" 5 "CSC 5" 6 "CSC 6" 31 "CSC31" ;
VAL_ 2400448121 BalDchg_PosCellLow_57 0 "No Discharging" 1 "Cell1 Discharging" 2 "Cell2 Discharging" 4 "Cell3 Discharging" 8 "Cell4 Discharging" 16 "Cell5 Discharging" 134217728 "Cell28 Discharging" 268435456 "Cell29 Discharging" ;
VAL_ 2400448121 BalDchg_PosCellHigh_57 0 "No Discharging" 1 "Cell1 Discharging" 2 "Cell2 Discharging" 4 "Cell3 Discharging" 8 "Cell4 Discharging" 16 "Cell5 Discharging" 134217728 "Cell28 Discharging" 268435456 "Cell29 Discharging" ;
VAL_ 2400448122 CSC_B_No_58 1 "CSC 1" 2 "CSC 2" 3 "CSC 3" 4 "CSC 4" 5 "CSC 5" 6 "CSC 6" 31 "CSC31" ;
VAL_ 2400448122 BalDchg_PosCellLow_58 0 "No Discharging" 1 "Cell1 Discharging" 2 "Cell2 Discharging" 4 "Cell3 Discharging" 8 "Cell4 Discharging" 16 "Cell5 Discharging" 134217728 "Cell28 Discharging" 268435456 "Cell29 Discharging" ;
VAL_ 2400448122 BalDchg_PosCellHigh_58 0 "No Discharging" 1 "Cell1 Discharging" 2 "Cell2 Discharging" 4 "Cell3 Discharging" 8 "Cell4 Discharging" 16 "Cell5 Discharging" 134217728 "Cell28 Discharging" 268435456 "Cell29 Discharging" ;
VAL_ 2400448123 CSC_B_No_59 1 "CSC 1" 2 "CSC 2" 3 "CSC 3" 4 "CSC 4" 5 "CSC 5" 6 "CSC 6" 31 "CSC31" ;
VAL_ 2400448123 BalDchg_PosCellLow_59 0 "No Discharging" 1 "Cell1 Discharging" 2 "Cell2 Discharging" 4 "Cell3 Discharging" 8 "Cell4 Discharging" 16 "Cell5 Discharging" 134217728 "Cell28 Discharging" 268435456 "Cell29 Discharging" ;
VAL_ 2400448123 BalDchg_PosCellHigh_59 0 "No Discharging" 1 "Cell1 Discharging" 2 "Cell2 Discharging" 4 "Cell3 Discharging" 8 "Cell4 Discharging" 16 "Cell5 Discharging" 134217728 "Cell28 Discharging" 268435456 "Cell29 Discharging" ;
VAL_ 2400448124 CSC_B_No_60 1 "CSC 1" 2 "CSC 2" 3 "CSC 3" 4 "CSC 4" 5 "CSC 5" 6 "CSC 6" 31 "CSC31" ;
VAL_ 2400448124 BalDchg_PosCellLow_60 0 "No Discharging" 1 "Cell1 Discharging" 2 "Cell2 Discharging" 4 "Cell3 Discharging" 8 "Cell4 Discharging" 16 "Cell5 Discharging" 134217728 "Cell28 Discharging" 268435456 "Cell29 Discharging" ;
VAL_ 2400448124 BalDchg_PosCellHigh_60 0 "No Discharging" 1 "Cell1 Discharging" 2 "Cell2 Discharging" 4 "Cell3 Discharging" 8 "Cell4 Discharging" 16 "Cell5 Discharging" 134217728 "Cell28 Discharging" 268435456 "Cell29 Discharging" ;
VAL_ 2400448125 CSC_B_No_61 1 "CSC 1" 2 "CSC 2" 3 "CSC 3" 4 "CSC 4" 5 "CSC 5" 6 "CSC 6" 31 "CSC31" ;
VAL_ 2400448125 BalDchg_PosCellLow_61 0 "No Discharging" 1 "Cell1 Discharging" 2 "Cell2 Discharging" 4 "Cell3 Discharging" 8 "Cell4 Discharging" 16 "Cell5 Discharging" 134217728 "Cell28 Discharging" 268435456 "Cell29 Discharging" ;
VAL_ 2400448125 BalDchg_PosCellHigh_61 0 "No Discharging" 1 "Cell1 Discharging" 2 "Cell2 Discharging" 4 "Cell3 Discharging" 8 "Cell4 Discharging" 16 "Cell5 Discharging" 134217728 "Cell28 Discharging" 268435456 "Cell29 Discharging" ;
VAL_ 2400448126 CSC_B_No_62 1 "CSC 1" 2 "CSC 2" 3 "CSC 3" 4 "CSC 4" 5 "CSC 5" 6 "CSC 6" 31 "CSC31" ;
VAL_ 2400448126 BalDchg_PosCellLow_62 0 "No Discharging" 1 "Cell1 Discharging" 2 "Cell2 Discharging" 4 "Cell3 Discharging" 8 "Cell4 Discharging" 16 "Cell5 Discharging" 134217728 "Cell28 Discharging" 268435456 "Cell29 Discharging" ;
VAL_ 2400448126 BalDchg_PosCellHigh_62 0 "No Discharging" 1 "Cell1 Discharging" 2 "Cell2 Discharging" 4 "Cell3 Discharging" 8 "Cell4 Discharging" 16 "Cell5 Discharging" 134217728 "Cell28 Discharging" 268435456 "Cell29 Discharging" ;
VAL_ 2400448127 CSC_B_No_63 1 "CSC 1" 2 "CSC 2" 3 "CSC 3" 4 "CSC 4" 5 "CSC 5" 6 "CSC 6" 31 "CSC31" ;
VAL_ 2400448127 BalDchg_PosCellLow_63 0 "No Discharging" 1 "Cell1 Discharging" 2 "Cell2 Discharging" 4 "Cell3 Discharging" 8 "Cell4 Discharging" 16 "Cell5 Discharging" 134217728 "Cell28 Discharging" 268435456 "Cell29 Discharging" ;
VAL_ 2400448127 BalDchg_PosCellHigh_63 0 "No Discharging" 1 "Cell1 Discharging" 2 "Cell2 Discharging" 4 "Cell3 Discharging" 8 "Cell4 Discharging" 16 "Cell5 Discharging" 134217728 "Cell28 Discharging" 268435456 "Cell29 Discharging" ;
VAL_ 2400579137 State_Balance_Status_01 0 "forbid balance" 1 "on balance" 2 "permit balance" 3 "balancing stopped" 4 "waitting for balance" ;
VAL_ 2400579137 State_Balance_Fault_01 0 "Normal" 1 "Failure" ;
VAL_ 2400579138 State_Balance_Status_02 0 "forbid balance" 1 "on balance" 2 "permit balance" 3 "balancing stopped" 4 "waitting for balance" ;
VAL_ 2400579138 State_Balance_Fault_02 0 "Normal" 1 "Failure" ;
VAL_ 2400579139 State_Balance_Status_03 0 "forbid balance" 1 "on balance" 2 "permit balance" 3 "balancing stopped" 4 "waitting for balance" ;
VAL_ 2400579139 State_Balance_Fault_03 0 "Normal" 1 "Failure" ;
VAL_ 2400579140 State_Balance_Status_04 0 "forbid balance" 1 "on balance" 2 "permit balance" 3 "balancing stopped" 4 "waitting for balance" ;
VAL_ 2400579140 State_Balance_Fault_04 0 "Normal" 1 "Failure" ;
VAL_ 2400579141 State_Balance_Status_05 0 "forbid balance" 1 "on balance" 2 "permit balance" 3 "balancing stopped" 4 "waitting for balance" ;
VAL_ 2400579141 State_Balance_Fault_05 0 "Normal" 1 "Failure" ;
VAL_ 2400579142 State_Balance_Status_06 0 "forbid balance" 1 "on balance" 2 "permit balance" 3 "balancing stopped" 4 "waitting for balance" ;
VAL_ 2400579142 State_Balance_Fault_06 0 "Normal" 1 "Failure" ;
VAL_ 2400579143 State_Balance_Status_07 0 "forbid balance" 1 "on balance" 2 "permit balance" 3 "balancing stopped" 4 "waitting for balance" ;
VAL_ 2400579143 State_Balance_Fault_07 0 "Normal" 1 "Failure" ;
VAL_ 2400579144 State_Balance_Status_08 0 "forbid balance" 1 "on balance" 2 "permit balance" 3 "balancing stopped" 4 "waitting for balance" ;
VAL_ 2400579144 State_Balance_Fault_08 0 "Normal" 1 "Failure" ;
VAL_ 2400579145 State_Balance_Status_09 0 "forbid balance" 1 "on balance" 2 "permit balance" 3 "balancing stopped" 4 "waitting for balance" ;
VAL_ 2400579145 State_Balance_Fault_09 0 "Normal" 1 "Failure" ;
VAL_ 2400579146 State_Balance_Status_10 0 "forbid balance" 1 "on balance" 2 "permit balance" 3 "balancing stopped" 4 "waitting for balance" ;
VAL_ 2400579146 State_Balance_Fault_10 0 "Normal" 1 "Failure" ;
VAL_ 2400579147 State_Balance_Status_11 0 "forbid balance" 1 "on balance" 2 "permit balance" 3 "balancing stopped" 4 "waitting for balance" ;
VAL_ 2400579147 State_Balance_Fault_11 0 "Normal" 1 "Failure" ;
VAL_ 2400579148 State_Balance_Status_12 0 "forbid balance" 1 "on balance" 2 "permit balance" 3 "balancing stopped" 4 "waitting for balance" ;
VAL_ 2400579148 State_Balance_Fault_12 0 "Normal" 1 "Failure" ;
VAL_ 2400579149 State_Balance_Status_13 0 "forbid balance" 1 "on balance" 2 "permit balance" 3 "balancing stopped" 4 "waitting for balance" ;
VAL_ 2400579149 State_Balance_Fault_13 0 "Normal" 1 "Failure" ;
VAL_ 2400579150 State_Balance_Status_14 0 "forbid balance" 1 "on balance" 2 "permit balance" 3 "balancing stopped" 4 "waitting for balance" ;
VAL_ 2400579150 State_Balance_Fault_14 0 "Normal" 1 "Failure" ;
VAL_ 2400579151 State_Balance_Status_15 0 "forbid balance" 1 "on balance" 2 "permit balance" 3 "balancing stopped" 4 "waitting for balance" ;
VAL_ 2400579151 State_Balance_Fault_15 0 "Normal" 1 "Failure" ;
VAL_ 2400579152 State_Balance_Status_16 0 "forbid balance" 1 "on balance" 2 "permit balance" 3 "balancing stopped" 4 "waitting for balance" ;
VAL_ 2400579152 State_Balance_Fault_16 0 "Normal" 1 "Failure" ;
VAL_ 2400579153 State_Balance_Status_17 0 "forbid balance" 1 "on balance" 2 "permit balance" 3 "balancing stopped" 4 "waitting for balance" ;
VAL_ 2400579153 State_Balance_Fault_17 0 "Normal" 1 "Failure" ;
VAL_ 2400579154 State_Balance_Status_18 0 "forbid balance" 1 "on balance" 2 "permit balance" 3 "balancing stopped" 4 "waitting for balance" ;
VAL_ 2400579154 State_Balance_Fault_18 0 "Normal" 1 "Failure" ;
VAL_ 2400579155 State_Balance_Status_19 0 "forbid balance" 1 "on balance" 2 "permit balance" 3 "balancing stopped" 4 "waitting for balance" ;
VAL_ 2400579155 State_Balance_Fault_19 0 "Normal" 1 "Failure" ;
VAL_ 2400579156 State_Balance_Status_20 0 "forbid balance" 1 "on balance" 2 "permit balance" 3 "balancing stopped" 4 "waitting for balance" ;
VAL_ 2400579156 State_Balance_Fault_20 0 "Normal" 1 "Failure" ;
VAL_ 2400579157 State_Balance_Status_21 0 "forbid balance" 1 "on balance" 2 "permit balance" 3 "balancing stopped" 4 "waitting for balance" ;
VAL_ 2400579157 State_Balance_Fault_21 0 "Normal" 1 "Failure" ;
VAL_ 2400579158 State_Balance_Status_22 0 "forbid balance" 1 "on balance" 2 "permit balance" 3 "balancing stopped" 4 "waitting for balance" ;
VAL_ 2400579158 State_Balance_Fault_22 0 "Normal" 1 "Failure" ;
VAL_ 2400579159 State_Balance_Status_23 0 "forbid balance" 1 "on balance" 2 "permit balance" 3 "balancing stopped" 4 "waitting for balance" ;
VAL_ 2400579159 State_Balance_Fault_23 0 "Normal" 1 "Failure" ;
VAL_ 2400579160 State_Balance_Status_24 0 "forbid balance" 1 "on balance" 2 "permit balance" 3 "balancing stopped" 4 "waitting for balance" ;
VAL_ 2400579160 State_Balance_Fault_24 0 "Normal" 1 "Failure" ;
VAL_ 2400579161 State_Balance_Status_25 0 "forbid balance" 1 "on balance" 2 "permit balance" 3 "balancing stopped" 4 "waitting for balance" ;
VAL_ 2400579161 State_Balance_Fault_25 0 "Normal" 1 "Failure" ;
VAL_ 2400579162 State_Balance_Status_26 0 "forbid balance" 1 "on balance" 2 "permit balance" 3 "balancing stopped" 4 "waitting for balance" ;
VAL_ 2400579162 State_Balance_Fault_26 0 "Normal" 1 "Failure" ;
VAL_ 2400579163 State_Balance_Status_27 0 "forbid balance" 1 "on balance" 2 "permit balance" 3 "balancing stopped" 4 "waitting for balance" ;
VAL_ 2400579163 State_Balance_Fault_27 0 "Normal" 1 "Failure" ;
VAL_ 2400579164 State_Balance_Status_28 0 "forbid balance" 1 "on balance" 2 "permit balance" 3 "balancing stopped" 4 "waitting for balance" ;
VAL_ 2400579164 State_Balance_Fault_28 0 "Normal" 1 "Failure" ;
VAL_ 2400579165 State_Balance_Status_29 0 "forbid balance" 1 "on balance" 2 "permit balance" 3 "balancing stopped" 4 "waitting for balance" ;
VAL_ 2400579165 State_Balance_Fault_29 0 "Normal" 1 "Failure" ;
VAL_ 2400579166 State_Balance_Status_30 0 "forbid balance" 1 "on balance" 2 "permit balance" 3 "balancing stopped" 4 "waitting for balance" ;
VAL_ 2400579166 State_Balance_Fault_30 0 "Normal" 1 "Failure" ;
VAL_ 2400579167 State_Balance_Status_31 0 "forbid balance" 1 "on balance" 2 "permit balance" 3 "balancing stopped" 4 "waitting for balance" ;
VAL_ 2400579167 State_Balance_Fault_31 0 "Normal" 1 "Failure" ;
VAL_ 2400579168 State_Balance_Status_32 0 "forbid balance" 1 "on balance" 2 "permit balance" 3 "balancing stopped" 4 "waitting for balance" ;
VAL_ 2400579168 State_Balance_Fault_32 0 "Normal" 1 "Failure" ;
VAL_ 2400579169 State_Balance_Status_33 0 "forbid balance" 1 "on balance" 2 "permit balance" 3 "balancing stopped" 4 "waitting for balance" ;
VAL_ 2400579169 State_Balance_Fault_33 0 "Normal" 1 "Failure" ;
VAL_ 2400579170 State_Balance_Status_34 0 "forbid balance" 1 "on balance" 2 "permit balance" 3 "balancing stopped" 4 "waitting for balance" ;
VAL_ 2400579170 State_Balance_Fault_34 0 "Normal" 1 "Failure" ;
VAL_ 2400579171 State_Balance_Status_35 0 "forbid balance" 1 "on balance" 2 "permit balance" 3 "balancing stopped" 4 "waitting for balance" ;
VAL_ 2400579171 State_Balance_Fault_35 0 "Normal" 1 "Failure" ;
VAL_ 2400579172 State_Balance_Status_36 0 "forbid balance" 1 "on balance" 2 "permit balance" 3 "balancing stopped" 4 "waitting for balance" ;
VAL_ 2400579172 State_Balance_Fault_36 0 "Normal" 1 "Failure" ;
VAL_ 2400579173 State_Balance_Status_37 0 "forbid balance" 1 "on balance" 2 "permit balance" 3 "balancing stopped" 4 "waitting for balance" ;
VAL_ 2400579173 State_Balance_Fault_37 0 "Normal" 1 "Failure" ;
VAL_ 2400579174 State_Balance_Status_38 0 "forbid balance" 1 "on balance" 2 "permit balance" 3 "balancing stopped" 4 "waitting for balance" ;
VAL_ 2400579174 State_Balance_Fault_38 0 "Normal" 1 "Failure" ;
VAL_ 2400579175 State_Balance_Status_39 0 "forbid balance" 1 "on balance" 2 "permit balance" 3 "balancing stopped" 4 "waitting for balance" ;
VAL_ 2400579175 State_Balance_Fault_39 0 "Normal" 1 "Failure" ;
VAL_ 2400579176 State_Balance_Status_40 0 "forbid balance" 1 "on balance" 2 "permit balance" 3 "balancing stopped" 4 "waitting for balance" ;
VAL_ 2400579176 State_Balance_Fault_40 0 "Normal" 1 "Failure" ;
VAL_ 2400579177 State_Balance_Status_41 0 "forbid balance" 1 "on balance" 2 "permit balance" 3 "balancing stopped" 4 "waitting for balance" ;
VAL_ 2400579177 State_Balance_Fault_41 0 "Normal" 1 "Failure" ;
VAL_ 2400579178 State_Balance_Status_42 0 "forbid balance" 1 "on balance" 2 "permit balance" 3 "balancing stopped" 4 "waitting for balance" ;
VAL_ 2400579178 State_Balance_Fault_42 0 "Normal" 1 "Failure" ;
VAL_ 2400579179 State_Balance_Status_43 0 "forbid balance" 1 "on balance" 2 "permit balance" 3 "balancing stopped" 4 "waitting for balance" ;
VAL_ 2400579179 State_Balance_Fault_43 0 "Normal" 1 "Failure" ;
VAL_ 2400579180 State_Balance_Status_44 0 "forbid balance" 1 "on balance" 2 "permit balance" 3 "balancing stopped" 4 "waitting for balance" ;
VAL_ 2400579180 State_Balance_Fault_44 0 "Normal" 1 "Failure" ;
VAL_ 2400579181 State_Balance_Status_45 0 "forbid balance" 1 "on balance" 2 "permit balance" 3 "balancing stopped" 4 "waitting for balance" ;
VAL_ 2400579181 State_Balance_Fault_45 0 "Normal" 1 "Failure" ;
VAL_ 2400579182 State_Balance_Status_46 0 "forbid balance" 1 "on balance" 2 "permit balance" 3 "balancing stopped" 4 "waitting for balance" ;
VAL_ 2400579182 State_Balance_Fault_46 0 "Normal" 1 "Failure" ;
VAL_ 2400579183 State_Balance_Status_47 0 "forbid balance" 1 "on balance" 2 "permit balance" 3 "balancing stopped" 4 "waitting for balance" ;
VAL_ 2400579183 State_Balance_Fault_47 0 "Normal" 1 "Failure" ;
VAL_ 2400579184 State_Balance_Status_48 0 "forbid balance" 1 "on balance" 2 "permit balance" 3 "balancing stopped" 4 "waitting for balance" ;
VAL_ 2400579184 State_Balance_Fault_48 0 "Normal" 1 "Failure" ;
VAL_ 2400579185 State_Balance_Status_49 0 "forbid balance" 1 "on balance" 2 "permit balance" 3 "balancing stopped" 4 "waitting for balance" ;
VAL_ 2400579185 State_Balance_Fault_49 0 "Normal" 1 "Failure" ;
VAL_ 2400579186 State_Balance_Status_50 0 "forbid balance" 1 "on balance" 2 "permit balance" 3 "balancing stopped" 4 "waitting for balance" ;
VAL_ 2400579186 State_Balance_Fault_50 0 "Normal" 1 "Failure" ;
VAL_ 2400579187 State_Balance_Status_51 0 "forbid balance" 1 "on balance" 2 "permit balance" 3 "balancing stopped" 4 "waitting for balance" ;
VAL_ 2400579187 State_Balance_Fault_51 0 "Normal" 1 "Failure" ;
VAL_ 2400579188 State_Balance_Status_52 0 "forbid balance" 1 "on balance" 2 "permit balance" 3 "balancing stopped" 4 "waitting for balance" ;
VAL_ 2400579188 State_Balance_Fault_52 0 "Normal" 1 "Failure" ;
VAL_ 2400579189 State_Balance_Status_53 0 "forbid balance" 1 "on balance" 2 "permit balance" 3 "balancing stopped" 4 "waitting for balance" ;
VAL_ 2400579189 State_Balance_Fault_53 0 "Normal" 1 "Failure" ;
VAL_ 2400579190 State_Balance_Status_54 0 "forbid balance" 1 "on balance" 2 "permit balance" 3 "balancing stopped" 4 "waitting for balance" ;
VAL_ 2400579190 State_Balance_Fault_54 0 "Normal" 1 "Failure" ;
VAL_ 2400579191 State_Balance_Status_55 0 "forbid balance" 1 "on balance" 2 "permit balance" 3 "balancing stopped" 4 "waitting for balance" ;
VAL_ 2400579191 State_Balance_Fault_55 0 "Normal" 1 "Failure" ;
VAL_ 2400579192 State_Balance_Status_56 0 "forbid balance" 1 "on balance" 2 "permit balance" 3 "balancing stopped" 4 "waitting for balance" ;
VAL_ 2400579192 State_Balance_Fault_56 0 "Normal" 1 "Failure" ;
VERSION ""

NS_ :

BS_:

BU_: MBMU PC SBMU IMM ETH DCDC LEMS

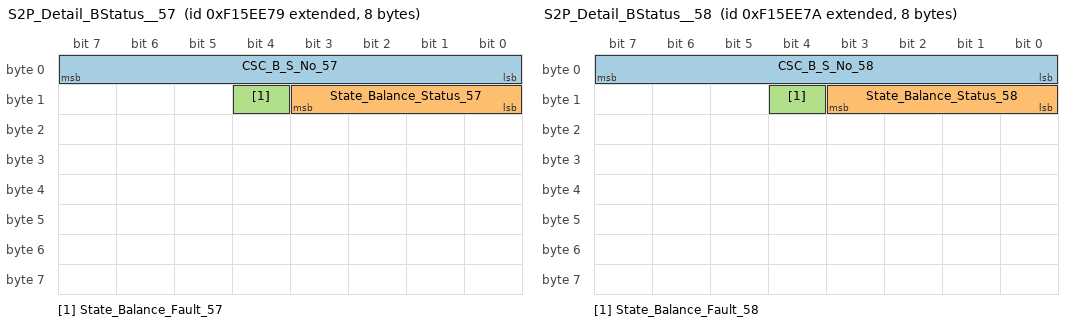
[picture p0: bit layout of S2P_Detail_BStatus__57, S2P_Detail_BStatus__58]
BO_ 2400579193 S2P_Detail_BStatus__57: 8 SBMU
 SG_ CSC_B_S_No_57 : 0|8@1+ (1,0) [0|255] ""  PC
 SG_ State_Balance_Status_57 : 8|4@1+ (1,0) [0|15] ""  PC
 SG_ State_Balance_Fault_57 : 12|1@1+ (1,0) [0|1] ""  PC

BO_ 2400579194 S2P_Detail_BStatus__58: 8 SBMU
 SG_ CSC_B_S_No_58 : 0|8@1+ (1,0) [0|255] ""  PC
 SG_ State_Balance_Status_58 : 8|4@1+ (1,0) [0|15] ""  PC
 SG_ State_Balance_Fault_58 : 12|1@1+ (1,0) [0|1] ""  PC

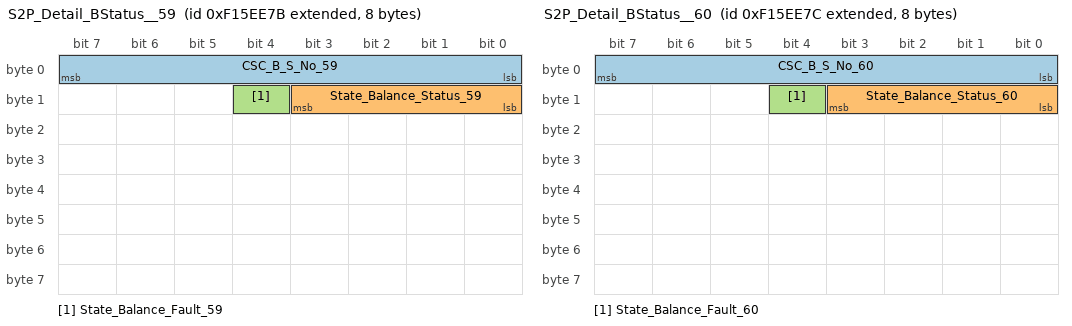
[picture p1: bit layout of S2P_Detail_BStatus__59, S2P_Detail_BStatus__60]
BO_ 2400579195 S2P_Detail_BStatus__59: 8 SBMU
 SG_ CSC_B_S_No_59 : 0|8@1+ (1,0) [0|255] ""  PC
 SG_ State_Balance_Status_59 : 8|4@1+ (1,0) [0|15] ""  PC
 SG_ State_Balance_Fault_59 : 12|1@1+ (1,0) [0|1] ""  PC

BO_ 2400579196 S2P_Detail_BStatus__60: 8 SBMU
 SG_ CSC_B_S_No_60 : 0|8@1+ (1,0) [0|255] ""  PC
 SG_ State_Balance_Status_60 : 8|4@1+ (1,0) [0|15] ""  PC
 SG_ State_Balance_Fault_60 : 12|1@1+ (1,0) [0|1] ""  PC

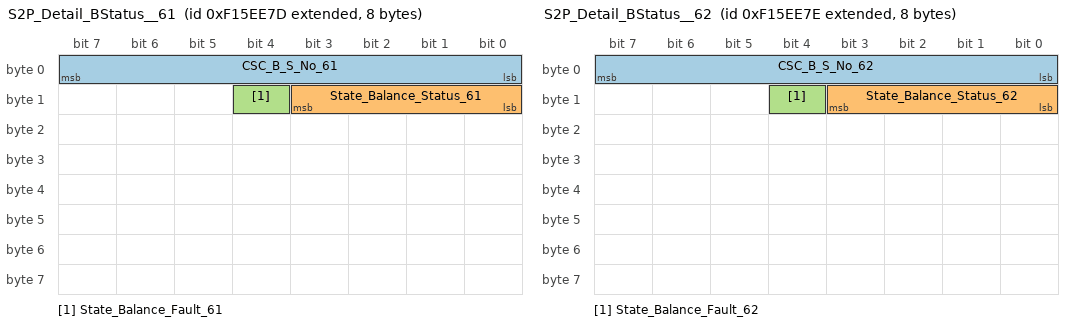
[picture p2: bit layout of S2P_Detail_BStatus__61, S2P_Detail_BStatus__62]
BO_ 2400579197 S2P_Detail_BStatus__61: 8 SBMU
 SG_ CSC_B_S_No_61 : 0|8@1+ (1,0) [0|255] ""  PC
 SG_ State_Balance_Status_61 : 8|4@1+ (1,0) [0|15] ""  PC
 SG_ State_Balance_Fault_61 : 12|1@1+ (1,0) [0|1] ""  PC

BO_ 2400579198 S2P_Detail_BStatus__62: 8 SBMU
 SG_ CSC_B_S_No_62 : 0|8@1+ (1,0) [0|255] ""  PC
 SG_ State_Balance_Status_62 : 8|4@1+ (1,0) [0|15] ""  PC
 SG_ State_Balance_Fault_62 : 12|1@1+ (1,0) [0|1] ""  PC

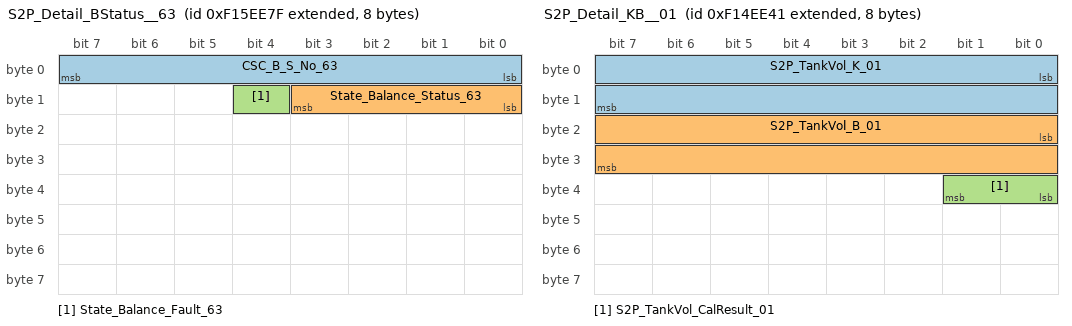
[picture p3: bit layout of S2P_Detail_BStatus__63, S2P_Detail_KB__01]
BO_ 2400579199 S2P_Detail_BStatus__63: 8 SBMU
 SG_ CSC_B_S_No_63 : 0|8@1+ (1,0) [0|255] ""  PC
 SG_ State_Balance_Status_63 : 8|4@1+ (1,0) [0|15] ""  PC
 SG_ State_Balance_Fault_63 : 12|1@1+ (1,0) [0|1] ""  PC

BO_ 2400513601 S2P_Detail_KB__01: 8 SBMU
 SG_ S2P_TankVol_K_01 : 0|16@1+ (0.001,0) [0|65.535] ""  PC
 SG_ S2P_TankVol_B_01 : 16|16@1+ (0.001,-30) [-30|35.535] "V"  PC
 SG_ S2P_TankVol_CalResult_01 : 32|2@1+ (1,0) [0|3] ""  PC

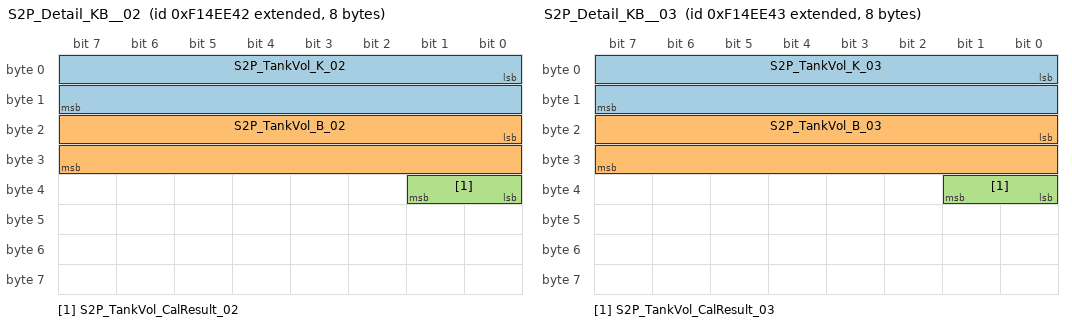
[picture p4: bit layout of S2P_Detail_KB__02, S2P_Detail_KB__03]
BO_ 2400513602 S2P_Detail_KB__02: 8 SBMU
 SG_ S2P_TankVol_K_02 : 0|16@1+ (0.001,0) [0|65.535] ""  PC
 SG_ S2P_TankVol_B_02 : 16|16@1+ (0.001,-30) [-30|35.535] "V"  PC
 SG_ S2P_TankVol_CalResult_02 : 32|2@1+ (1,0) [0|3] ""  PC

BO_ 2400513603 S2P_Detail_KB__03: 8 SBMU
 SG_ S2P_TankVol_K_03 : 0|16@1+ (0.001,0) [0|65.535] ""  PC
 SG_ S2P_TankVol_B_03 : 16|16@1+ (0.001,-30) [-30|35.535] "V"  PC
 SG_ S2P_TankVol_CalResult_03 : 32|2@1+ (1,0) [0|3] ""  PC

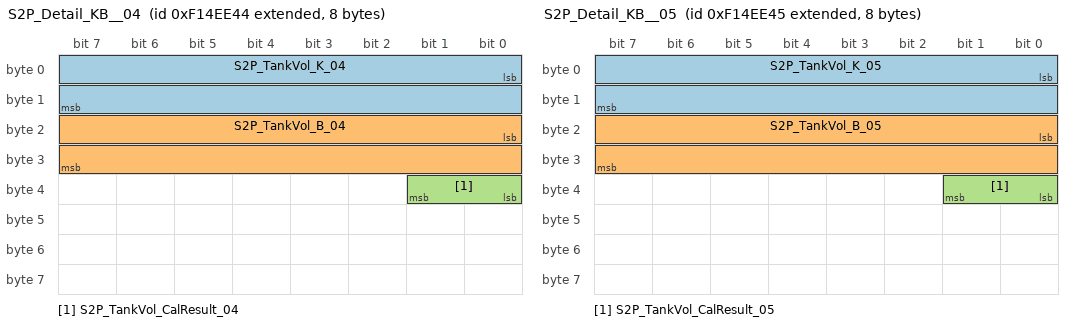
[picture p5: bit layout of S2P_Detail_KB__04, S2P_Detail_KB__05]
BO_ 2400513604 S2P_Detail_KB__04: 8 SBMU
 SG_ S2P_TankVol_K_04 : 0|16@1+ (0.001,0) [0|65.535] ""  PC
 SG_ S2P_TankVol_B_04 : 16|16@1+ (0.001,-30) [-30|35.535] "V"  PC
 SG_ S2P_TankVol_CalResult_04 : 32|2@1+ (1,0) [0|3] ""  PC

BO_ 2400513605 S2P_Detail_KB__05: 8 SBMU
 SG_ S2P_TankVol_K_05 : 0|16@1+ (0.001,0) [0|65.535] ""  PC
 SG_ S2P_TankVol_B_05 : 16|16@1+ (0.001,-30) [-30|35.535] "V"  PC
 SG_ S2P_TankVol_CalResult_05 : 32|2@1+ (1,0) [0|3] ""  PC

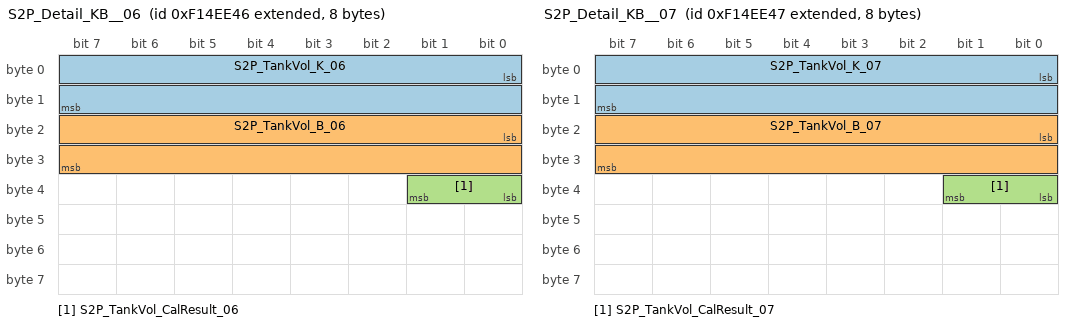
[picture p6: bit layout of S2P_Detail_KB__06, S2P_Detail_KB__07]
BO_ 2400513606 S2P_Detail_KB__06: 8 SBMU
 SG_ S2P_TankVol_K_06 : 0|16@1+ (0.001,0) [0|65.535] ""  PC
 SG_ S2P_TankVol_B_06 : 16|16@1+ (0.001,-30) [-30|35.535] "V"  PC
 SG_ S2P_TankVol_CalResult_06 : 32|2@1+ (1,0) [0|3] ""  PC

BO_ 2400513607 S2P_Detail_KB__07: 8 SBMU
 SG_ S2P_TankVol_K_07 : 0|16@1+ (0.001,0) [0|65.535] ""  PC
 SG_ S2P_TankVol_B_07 : 16|16@1+ (0.001,-30) [-30|35.535] "V"  PC
 SG_ S2P_TankVol_CalResult_07 : 32|2@1+ (1,0) [0|3] ""  PC

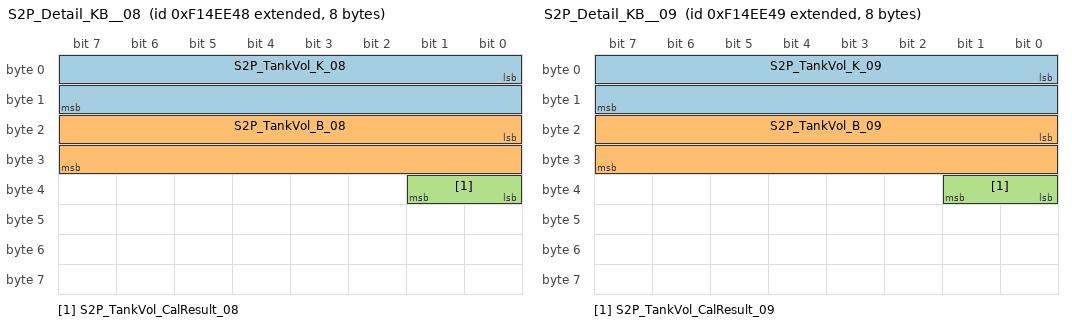
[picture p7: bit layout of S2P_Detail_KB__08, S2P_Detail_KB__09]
BO_ 2400513608 S2P_Detail_KB__08: 8 SBMU
 SG_ S2P_TankVol_K_08 : 0|16@1+ (0.001,0) [0|65.535] ""  PC
 SG_ S2P_TankVol_B_08 : 16|16@1+ (0.001,-30) [-30|35.535] "V"  PC
 SG_ S2P_TankVol_CalResult_08 : 32|2@1+ (1,0) [0|3] ""  PC

BO_ 2400513609 S2P_Detail_KB__09: 8 SBMU
 SG_ S2P_TankVol_K_09 : 0|16@1+ (0.001,0) [0|65.535] ""  PC
 SG_ S2P_TankVol_B_09 : 16|16@1+ (0.001,-30) [-30|35.535] "V"  PC
 SG_ S2P_TankVol_CalResult_09 : 32|2@1+ (1,0) [0|3] ""  PC

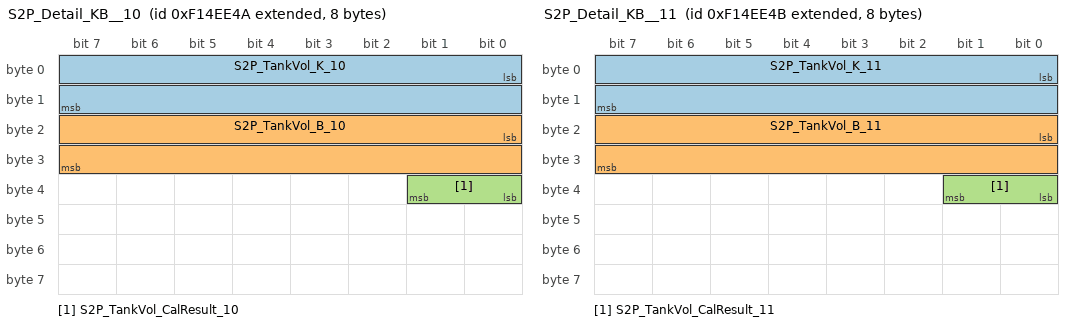
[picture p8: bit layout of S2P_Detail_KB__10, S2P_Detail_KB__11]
BO_ 2400513610 S2P_Detail_KB__10: 8 SBMU
 SG_ S2P_TankVol_K_10 : 0|16@1+ (0.001,0) [0|65.535] ""  PC
 SG_ S2P_TankVol_B_10 : 16|16@1+ (0.001,-30) [-30|35.535] "V"  PC
 SG_ S2P_TankVol_CalResult_10 : 32|2@1+ (1,0) [0|3] ""  PC

BO_ 2400513611 S2P_Detail_KB__11: 8 SBMU
 SG_ S2P_TankVol_K_11 : 0|16@1+ (0.001,0) [0|65.535] ""  PC
 SG_ S2P_TankVol_B_11 : 16|16@1+ (0.001,-30) [-30|35.535] "V"  PC
 SG_ S2P_TankVol_CalResult_11 : 32|2@1+ (1,0) [0|3] ""  PC

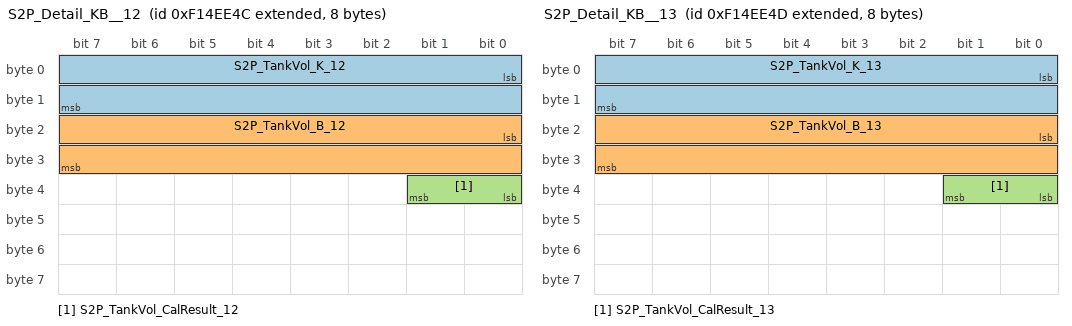
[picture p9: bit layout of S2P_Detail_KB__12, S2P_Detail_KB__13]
BO_ 2400513612 S2P_Detail_KB__12: 8 SBMU
 SG_ S2P_TankVol_K_12 : 0|16@1+ (0.001,0) [0|65.535] ""  PC
 SG_ S2P_TankVol_B_12 : 16|16@1+ (0.001,-30) [-30|35.535] "V"  PC
 SG_ S2P_TankVol_CalResult_12 : 32|2@1+ (1,0) [0|3] ""  PC

BO_ 2400513613 S2P_Detail_KB__13: 8 SBMU
 SG_ S2P_TankVol_K_13 : 0|16@1+ (0.001,0) [0|65.535] ""  PC
 SG_ S2P_TankVol_B_13 : 16|16@1+ (0.001,-30) [-30|35.535] "V"  PC
 SG_ S2P_TankVol_CalResult_13 : 32|2@1+ (1,0) [0|3] ""  PC

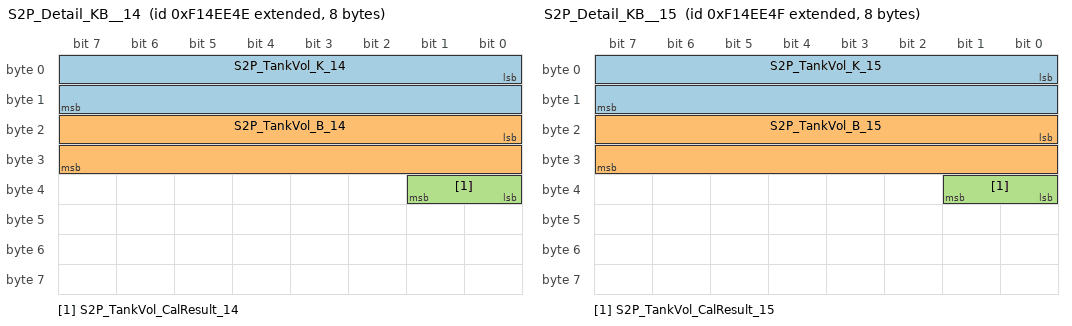
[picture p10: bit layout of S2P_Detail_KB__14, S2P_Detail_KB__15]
BO_ 2400513614 S2P_Detail_KB__14: 8 SBMU
 SG_ S2P_TankVol_K_14 : 0|16@1+ (0.001,0) [0|65.535] ""  PC
 SG_ S2P_TankVol_B_14 : 16|16@1+ (0.001,-30) [-30|35.535] "V"  PC
 SG_ S2P_TankVol_CalResult_14 : 32|2@1+ (1,0) [0|3] ""  PC

BO_ 2400513615 S2P_Detail_KB__15: 8 SBMU
 SG_ S2P_TankVol_K_15 : 0|16@1+ (0.001,0) [0|65.535] ""  PC
 SG_ S2P_TankVol_B_15 : 16|16@1+ (0.001,-30) [-30|35.535] "V"  PC
 SG_ S2P_TankVol_CalResult_15 : 32|2@1+ (1,0) [0|3] ""  PC

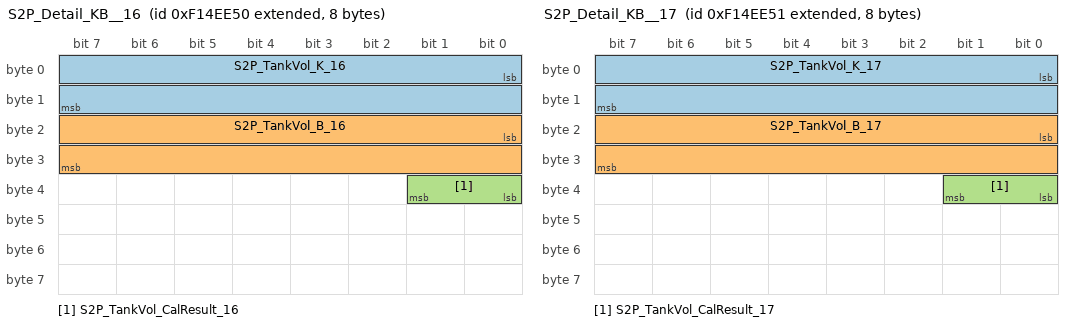
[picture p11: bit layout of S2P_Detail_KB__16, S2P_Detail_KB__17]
BO_ 2400513616 S2P_Detail_KB__16: 8 SBMU
 SG_ S2P_TankVol_K_16 : 0|16@1+ (0.001,0) [0|65.535] ""  PC
 SG_ S2P_TankVol_B_16 : 16|16@1+ (0.001,-30) [-30|35.535] "V"  PC
 SG_ S2P_TankVol_CalResult_16 : 32|2@1+ (1,0) [0|3] ""  PC

BO_ 2400513617 S2P_Detail_KB__17: 8 SBMU
 SG_ S2P_TankVol_K_17 : 0|16@1+ (0.001,0) [0|65.535] ""  PC
 SG_ S2P_TankVol_B_17 : 16|16@1+ (0.001,-30) [-30|35.535] "V"  PC
 SG_ S2P_TankVol_CalResult_17 : 32|2@1+ (1,0) [0|3] ""  PC

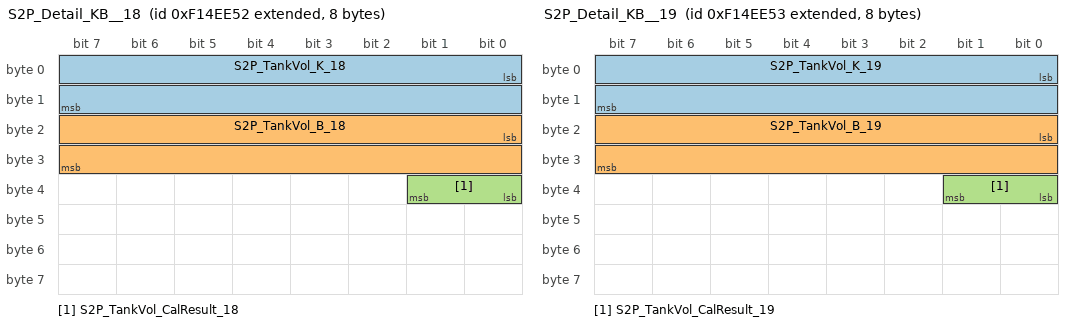
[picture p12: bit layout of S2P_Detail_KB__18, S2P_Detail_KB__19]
BO_ 2400513618 S2P_Detail_KB__18: 8 SBMU
 SG_ S2P_TankVol_K_18 : 0|16@1+ (0.001,0) [0|65.535] ""  PC
 SG_ S2P_TankVol_B_18 : 16|16@1+ (0.001,-30) [-30|35.535] "V"  PC
 SG_ S2P_TankVol_CalResult_18 : 32|2@1+ (1,0) [0|3] ""  PC

BO_ 2400513619 S2P_Detail_KB__19: 8 SBMU
 SG_ S2P_TankVol_K_19 : 0|16@1+ (0.001,0) [0|65.535] ""  PC
 SG_ S2P_TankVol_B_19 : 16|16@1+ (0.001,-30) [-30|35.535] "V"  PC
 SG_ S2P_TankVol_CalResult_19 : 32|2@1+ (1,0) [0|3] ""  PC

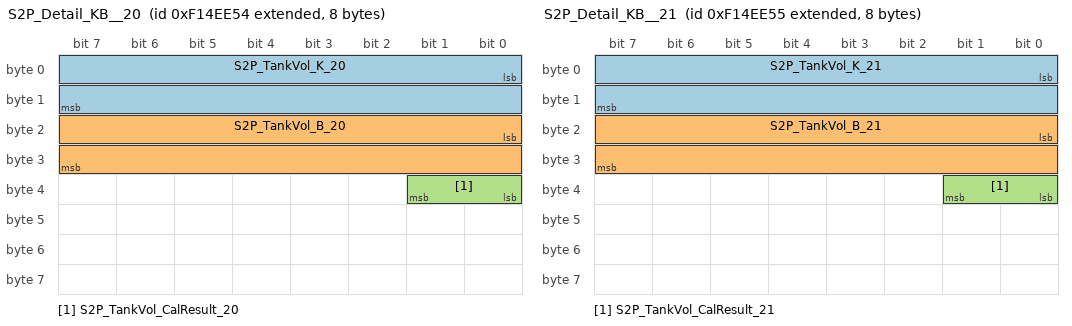
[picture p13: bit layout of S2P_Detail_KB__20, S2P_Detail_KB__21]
BO_ 2400513620 S2P_Detail_KB__20: 8 SBMU
 SG_ S2P_TankVol_K_20 : 0|16@1+ (0.001,0) [0|65.535] ""  PC
 SG_ S2P_TankVol_B_20 : 16|16@1+ (0.001,-30) [-30|35.535] "V"  PC
 SG_ S2P_TankVol_CalResult_20 : 32|2@1+ (1,0) [0|3] ""  PC

BO_ 2400513621 S2P_Detail_KB__21: 8 SBMU
 SG_ S2P_TankVol_K_21 : 0|16@1+ (0.001,0) [0|65.535] ""  PC
 SG_ S2P_TankVol_B_21 : 16|16@1+ (0.001,-30) [-30|35.535] "V"  PC
 SG_ S2P_TankVol_CalResult_21 : 32|2@1+ (1,0) [0|3] ""  PC

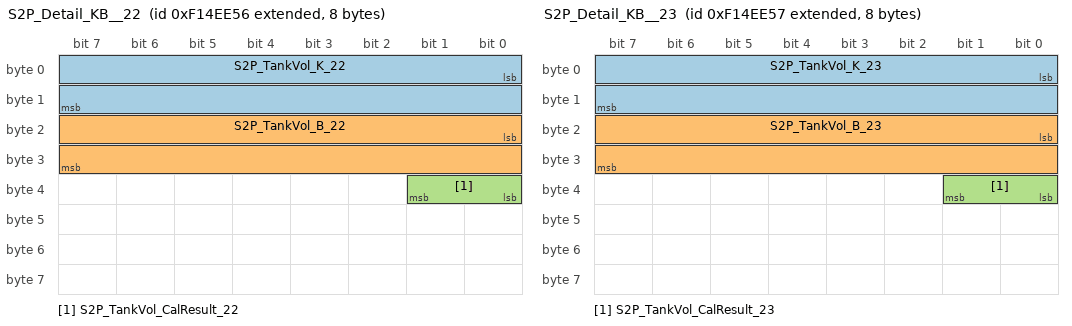
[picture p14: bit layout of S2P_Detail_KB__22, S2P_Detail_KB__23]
BO_ 2400513622 S2P_Detail_KB__22: 8 SBMU
 SG_ S2P_TankVol_K_22 : 0|16@1+ (0.001,0) [0|65.535] ""  PC
 SG_ S2P_TankVol_B_22 : 16|16@1+ (0.001,-30) [-30|35.535] "V"  PC
 SG_ S2P_TankVol_CalResult_22 : 32|2@1+ (1,0) [0|3] ""  PC

BO_ 2400513623 S2P_Detail_KB__23: 8 SBMU
 SG_ S2P_TankVol_K_23 : 0|16@1+ (0.001,0) [0|65.535] ""  PC
 SG_ S2P_TankVol_B_23 : 16|16@1+ (0.001,-30) [-30|35.535] "V"  PC
 SG_ S2P_TankVol_CalResult_23 : 32|2@1+ (1,0) [0|3] ""  PC

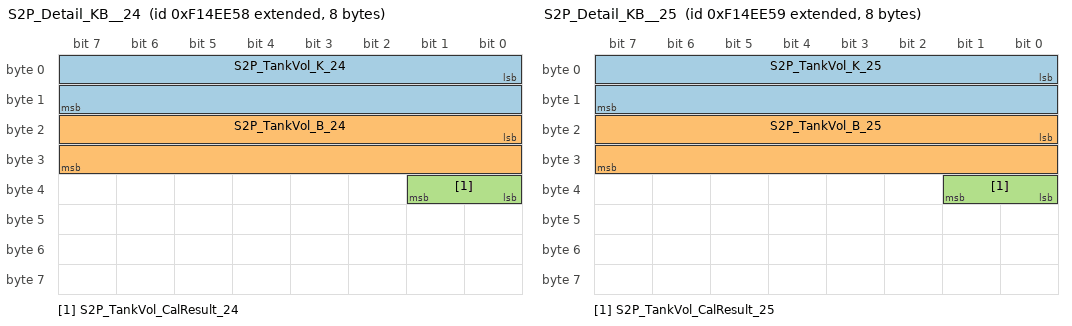
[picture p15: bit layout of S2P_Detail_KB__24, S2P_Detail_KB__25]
BO_ 2400513624 S2P_Detail_KB__24: 8 SBMU
 SG_ S2P_TankVol_K_24 : 0|16@1+ (0.001,0) [0|65.535] ""  PC
 SG_ S2P_TankVol_B_24 : 16|16@1+ (0.001,-30) [-30|35.535] "V"  PC
 SG_ S2P_TankVol_CalResult_24 : 32|2@1+ (1,0) [0|3] ""  PC

BO_ 2400513625 S2P_Detail_KB__25: 8 SBMU
 SG_ S2P_TankVol_K_25 : 0|16@1+ (0.001,0) [0|65.535] ""  PC
 SG_ S2P_TankVol_B_25 : 16|16@1+ (0.001,-30) [-30|35.535] "V"  PC
 SG_ S2P_TankVol_CalResult_25 : 32|2@1+ (1,0) [0|3] ""  PC

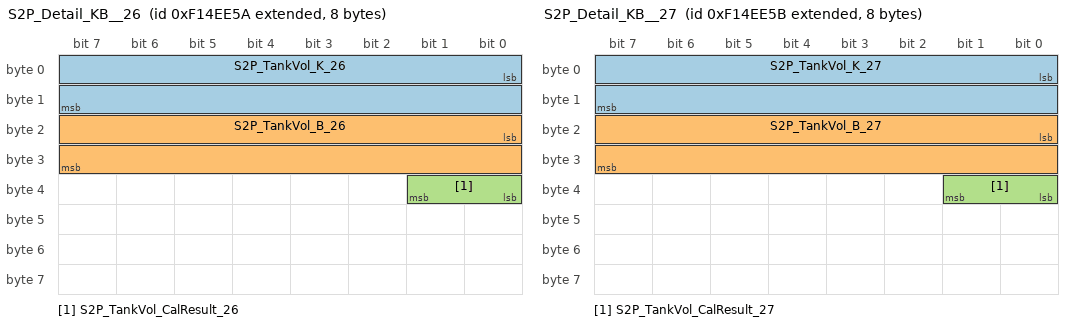
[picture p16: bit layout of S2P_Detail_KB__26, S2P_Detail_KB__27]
BO_ 2400513626 S2P_Detail_KB__26: 8 SBMU
 SG_ S2P_TankVol_K_26 : 0|16@1+ (0.001,0) [0|65.535] ""  PC
 SG_ S2P_TankVol_B_26 : 16|16@1+ (0.001,-30) [-30|35.535] "V"  PC
 SG_ S2P_TankVol_CalResult_26 : 32|2@1+ (1,0) [0|3] ""  PC

BO_ 2400513627 S2P_Detail_KB__27: 8 SBMU
 SG_ S2P_TankVol_K_27 : 0|16@1+ (0.001,0) [0|65.535] ""  PC
 SG_ S2P_TankVol_B_27 : 16|16@1+ (0.001,-30) [-30|35.535] "V"  PC
 SG_ S2P_TankVol_CalResult_27 : 32|2@1+ (1,0) [0|3] ""  PC

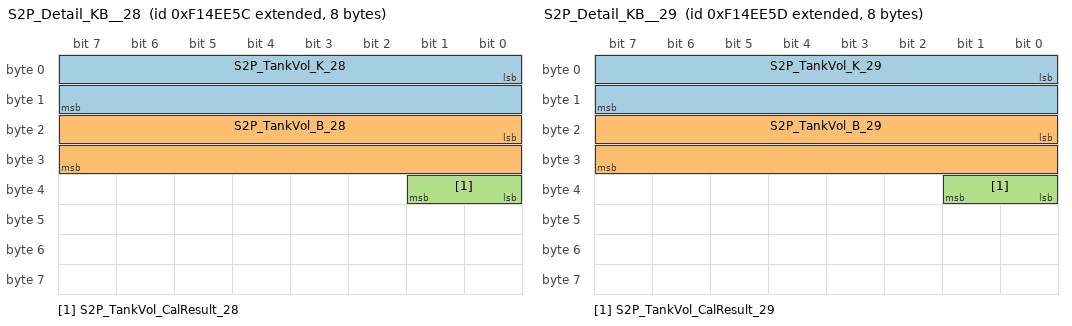
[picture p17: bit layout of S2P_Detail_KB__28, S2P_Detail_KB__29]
BO_ 2400513628 S2P_Detail_KB__28: 8 SBMU
 SG_ S2P_TankVol_K_28 : 0|16@1+ (0.001,0) [0|65.535] ""  PC
 SG_ S2P_TankVol_B_28 : 16|16@1+ (0.001,-30) [-30|35.535] "V"  PC
 SG_ S2P_TankVol_CalResult_28 : 32|2@1+ (1,0) [0|3] ""  PC

BO_ 2400513629 S2P_Detail_KB__29: 8 SBMU
 SG_ S2P_TankVol_K_29 : 0|16@1+ (0.001,0) [0|65.535] ""  PC
 SG_ S2P_TankVol_B_29 : 16|16@1+ (0.001,-30) [-30|35.535] "V"  PC
 SG_ S2P_TankVol_CalResult_29 : 32|2@1+ (1,0) [0|3] ""  PC

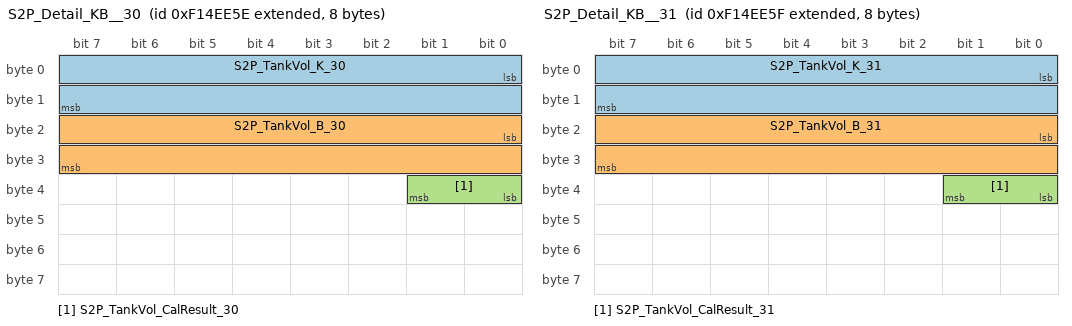
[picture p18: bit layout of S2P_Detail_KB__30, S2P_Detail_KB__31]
BO_ 2400513630 S2P_Detail_KB__30: 8 SBMU
 SG_ S2P_TankVol_K_30 : 0|16@1+ (0.001,0) [0|65.535] ""  PC
 SG_ S2P_TankVol_B_30 : 16|16@1+ (0.001,-30) [-30|35.535] "V"  PC
 SG_ S2P_TankVol_CalResult_30 : 32|2@1+ (1,0) [0|3] ""  PC

BO_ 2400513631 S2P_Detail_KB__31: 8 SBMU
 SG_ S2P_TankVol_K_31 : 0|16@1+ (0.001,0) [0|65.535] ""  PC
 SG_ S2P_TankVol_B_31 : 16|16@1+ (0.001,-30) [-30|35.535] "V"  PC
 SG_ S2P_TankVol_CalResult_31 : 32|2@1+ (1,0) [0|3] ""  PC

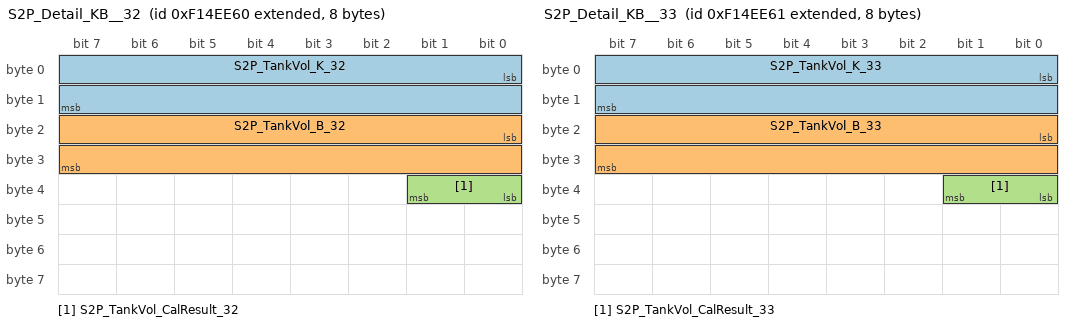
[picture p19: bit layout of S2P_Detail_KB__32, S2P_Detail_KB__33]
BO_ 2400513632 S2P_Detail_KB__32: 8 SBMU
 SG_ S2P_TankVol_K_32 : 0|16@1+ (0.001,0) [0|65.535] ""  PC
 SG_ S2P_TankVol_B_32 : 16|16@1+ (0.001,-30) [-30|35.535] "V"  PC
 SG_ S2P_TankVol_CalResult_32 : 32|2@1+ (1,0) [0|3] ""  PC

BO_ 2400513633 S2P_Detail_KB__33: 8 SBMU
 SG_ S2P_TankVol_K_33 : 0|16@1+ (0.001,0) [0|65.535] ""  PC
 SG_ S2P_TankVol_B_33 : 16|16@1+ (0.001,-30) [-30|35.535] "V"  PC
 SG_ S2P_TankVol_CalResult_33 : 32|2@1+ (1,0) [0|3] ""  PC

BO_ 2400513634 S2P_Detail_KB__34: 8 SBMU
 SG_ S2P_TankVol_K_34 : 0|16@1+ (0.001,0) [0|65.535] ""  PC
 SG_ S2P_TankVol_B_34 : 16|16@1+ (0.001,-30) [-30|35.535] "V"  PC
 SG_ S2P_TankVol_CalResult_34 : 32|2@1+ (1,0) [0|3] ""  PC

BO_ 2400513635 S2P_Detail_KB__35: 8 SBMU
 SG_ S2P_TankVol_K_35 : 0|16@1+ (0.001,0) [0|65.535] ""  PC
 SG_ S2P_TankVol_B_35 : 16|16@1+ (0.001,-30) [-30|35.535] "V"  PC
 SG_ S2P_TankVol_CalResult_35 : 32|2@1+ (1,0) [0|3] ""  PC

BO_ 2400513636 S2P_Detail_KB__36: 8 SBMU
 SG_ S2P_TankVol_K_36 : 0|16@1+ (0.001,0) [0|65.535] ""  PC
 SG_ S2P_TankVol_B_36 : 16|16@1+ (0.001,-30) [-30|35.535] "V"  PC
 SG_ S2P_TankVol_CalResult_36 : 32|2@1+ (1,0) [0|3] ""  PC

BO_ 2400513637 S2P_Detail_KB__37: 8 SBMU
 SG_ S2P_TankVol_K_37 : 0|16@1+ (0.001,0) [0|65.535] ""  PC
 SG_ S2P_TankVol_B_37 : 16|16@1+ (0.001,-30) [-30|35.535] "V"  PC
 SG_ S2P_TankVol_CalResult_37 : 32|2@1+ (1,0) [0|3] ""  PC

BO_ 2400513638 S2P_Detail_KB__38: 8 SBMU
 SG_ S2P_TankVol_K_38 : 0|16@1+ (0.001,0) [0|65.535] ""  PC
 SG_ S2P_TankVol_B_38 : 16|16@1+ (0.001,-30) [-30|35.535] "V"  PC
 SG_ S2P_TankVol_CalResult_38 : 32|2@1+ (1,0) [0|3] ""  PC

BO_ 2400513639 S2P_Detail_KB__39: 8 SBMU
 SG_ S2P_TankVol_K_39 : 0|16@1+ (0.001,0) [0|65.535] ""  PC
 SG_ S2P_TankVol_B_39 : 16|16@1+ (0.001,-30) [-30|35.535] "V"  PC
 SG_ S2P_TankVol_CalResult_39 : 32|2@1+ (1,0) [0|3] ""  PC

BO_ 2400513640 S2P_Detail_KB__40: 8 SBMU
 SG_ S2P_TankVol_K_40 : 0|16@1+ (0.001,0) [0|65.535] ""  PC
 SG_ S2P_TankVol_B_40 : 16|16@1+ (0.001,-30) [-30|35.535] "V"  PC
 SG_ S2P_TankVol_CalResult_40 : 32|2@1+ (1,0) [0|3] ""  PC

BO_ 2400513641 S2P_Detail_KB__41: 8 SBMU
 SG_ S2P_TankVol_K_41 : 0|16@1+ (0.001,0) [0|65.535] ""  PC
 SG_ S2P_TankVol_B_41 : 16|16@1+ (0.001,-30) [-30|35.535] "V"  PC
 SG_ S2P_TankVol_CalResult_41 : 32|2@1+ (1,0) [0|3] ""  PC

BO_ 2400513642 S2P_Detail_KB__42: 8 SBMU
 SG_ S2P_TankVol_K_42 : 0|16@1+ (0.001,0) [0|65.535] ""  PC
 SG_ S2P_TankVol_B_42 : 16|16@1+ (0.001,-30) [-30|35.535] "V"  PC
 SG_ S2P_TankVol_CalResult_42 : 32|2@1+ (1,0) [0|3] ""  PC

BO_ 2400513643 S2P_Detail_KB__43: 8 SBMU
 SG_ S2P_TankVol_K_43 : 0|16@1+ (0.001,0) [0|65.535] ""  PC
 SG_ S2P_TankVol_B_43 : 16|16@1+ (0.001,-30) [-30|35.535] "V"  PC
 SG_ S2P_TankVol_CalResult_43 : 32|2@1+ (1,0) [0|3] ""  PC

BO_ 2400513644 S2P_Detail_KB__44: 8 SBMU
 SG_ S2P_TankVol_K_44 : 0|16@1+ (0.001,0) [0|65.535] ""  PC
 SG_ S2P_TankVol_B_44 : 16|16@1+ (0.001,-30) [-30|35.535] "V"  PC
 SG_ S2P_TankVol_CalResult_44 : 32|2@1+ (1,0) [0|3] ""  PC

BO_ 2400513645 S2P_Detail_KB__45: 8 SBMU
 SG_ S2P_TankVol_K_45 : 0|16@1+ (0.001,0) [0|65.535] ""  PC
 SG_ S2P_TankVol_B_45 : 16|16@1+ (0.001,-30) [-30|35.535] "V"  PC
 SG_ S2P_TankVol_CalResult_45 : 32|2@1+ (1,0) [0|3] ""  PC

BO_ 2400513646 S2P_Detail_KB__46: 8 SBMU
 SG_ S2P_TankVol_K_46 : 0|16@1+ (0.001,0) [0|65.535] ""  PC
 SG_ S2P_TankVol_B_46 : 16|16@1+ (0.001,-30) [-30|35.535] "V"  PC
 SG_ S2P_TankVol_CalResult_46 : 32|2@1+ (1,0) [0|3] ""  PC

BO_ 2400513647 S2P_Detail_KB__47: 8 SBMU
 SG_ S2P_TankVol_K_47 : 0|16@1+ (0.001,0) [0|65.535] ""  PC
 SG_ S2P_TankVol_B_47 : 16|16@1+ (0.001,-30) [-30|35.535] "V"  PC
 SG_ S2P_TankVol_CalResult_47 : 32|2@1+ (1,0) [0|3] ""  PC

BO_ 2400513648 S2P_Detail_KB__48: 8 SBMU
 SG_ S2P_TankVol_K_48 : 0|16@1+ (0.001,0) [0|65.535] ""  PC
 SG_ S2P_TankVol_B_48 : 16|16@1+ (0.001,-30) [-30|35.535] "V"  PC
 SG_ S2P_TankVol_CalResult_48 : 32|2@1+ (1,0) [0|3] ""  PC

BO_ 2400513649 S2P_Detail_KB__49: 8 SBMU
 SG_ S2P_TankVol_K_49 : 0|16@1+ (0.001,0) [0|65.535] ""  PC
 SG_ S2P_TankVol_B_49 : 16|16@1+ (0.001,-30) [-30|35.535] "V"  PC
 SG_ S2P_TankVol_CalResult_49 : 32|2@1+ (1,0) [0|3] ""  PC

BO_ 2400513650 S2P_Detail_KB__50: 8 SBMU
 SG_ S2P_TankVol_K_50 : 0|16@1+ (0.001,0) [0|65.535] ""  PC
 SG_ S2P_TankVol_B_50 : 16|16@1+ (0.001,-30) [-30|35.535] "V"  PC
 SG_ S2P_TankVol_CalResult_50 : 32|2@1+ (1,0) [0|3] ""  PC

BO_ 2400513651 S2P_Detail_KB__51: 8 SBMU
 SG_ S2P_TankVol_K_51 : 0|16@1+ (0.001,0) [0|65.535] ""  PC
 SG_ S2P_TankVol_B_51 : 16|16@1+ (0.001,-30) [-30|35.535] "V"  PC
 SG_ S2P_TankVol_CalResult_51 : 32|2@1+ (1,0) [0|3] ""  PC

BO_ 2400513652 S2P_Detail_KB__52: 8 SBMU
 SG_ S2P_TankVol_K_52 : 0|16@1+ (0.001,0) [0|65.535] ""  PC
 SG_ S2P_TankVol_B_52 : 16|16@1+ (0.001,-30) [-30|35.535] "V"  PC
 SG_ S2P_TankVol_CalResult_52 : 32|2@1+ (1,0) [0|3] ""  PC

BO_ 2400513653 S2P_Detail_KB__53: 8 SBMU
 SG_ S2P_TankVol_K_53 : 0|16@1+ (0.001,0) [0|65.535] ""  PC
 SG_ S2P_TankVol_B_53 : 16|16@1+ (0.001,-30) [-30|35.535] "V"  PC
 SG_ S2P_TankVol_CalResult_53 : 32|2@1+ (1,0) [0|3] ""  PC

BO_ 2400513654 S2P_Detail_KB__54: 8 SBMU
 SG_ S2P_TankVol_K_54 : 0|16@1+ (0.001,0) [0|65.535] ""  PC
 SG_ S2P_TankVol_B_54 : 16|16@1+ (0.001,-30) [-30|35.535] "V"  PC
 SG_ S2P_TankVol_CalResult_54 : 32|2@1+ (1,0) [0|3] ""  PC

BO_ 2400513655 S2P_Detail_KB__55: 8 SBMU
 SG_ S2P_TankVol_K_55 : 0|16@1+ (0.001,0) [0|65.535] ""  PC
 SG_ S2P_TankVol_B_55 : 16|16@1+ (0.001,-30) [-30|35.535] "V"  PC
 SG_ S2P_TankVol_CalResult_55 : 32|2@1+ (1,0) [0|3] ""  PC

BO_ 2400513656 S2P_Detail_KB__56: 8 SBMU
 SG_ S2P_TankVol_K_56 : 0|16@1+ (0.001,0) [0|65.535] ""  PC
 SG_ S2P_TankVol_B_56 : 16|16@1+ (0.001,-30) [-30|35.535] "V"  PC
 SG_ S2P_TankVol_CalResult_56 : 32|2@1+ (1,0) [0|3] ""  PC

BO_ 2400513657 S2P_Detail_KB__57: 8 SBMU
 SG_ S2P_TankVol_K_57 : 0|16@1+ (0.001,0) [0|65.535] ""  PC
 SG_ S2P_TankVol_B_57 : 16|16@1+ (0.001,-30) [-30|35.535] "V"  PC
 SG_ S2P_TankVol_CalResult_57 : 32|2@1+ (1,0) [0|3] ""  PC

BO_ 2400513658 S2P_Detail_KB__58: 8 SBMU
 SG_ S2P_TankVol_K_58 : 0|16@1+ (0.001,0) [0|65.535] ""  PC
 SG_ S2P_TankVol_B_58 : 16|16@1+ (0.001,-30) [-30|35.535] "V"  PC
 SG_ S2P_TankVol_CalResult_58 : 32|2@1+ (1,0) [0|3] ""  PC

BO_ 2400513659 S2P_Detail_KB__59: 8 SBMU
 SG_ S2P_TankVol_K_59 : 0|16@1+ (0.001,0) [0|65.535] ""  PC
 SG_ S2P_TankVol_B_59 : 16|16@1+ (0.001,-30) [-30|35.535] "V"  PC
 SG_ S2P_TankVol_CalResult_59 : 32|2@1+ (1,0) [0|3] ""  PC

BO_ 2400513660 S2P_Detail_KB__60: 8 SBMU
 SG_ S2P_TankVol_K_60 : 0|16@1+ (0.001,0) [0|65.535] ""  PC
 SG_ S2P_TankVol_B_60 : 16|16@1+ (0.001,-30) [-30|35.535] "V"  PC
 SG_ S2P_TankVol_CalResult_60 : 32|2@1+ (1,0) [0|3] ""  PC

BO_ 2400513661 S2P_Detail_KB__61: 8 SBMU
 SG_ S2P_TankVol_K_61 : 0|16@1+ (0.001,0) [0|65.535] ""  PC
 SG_ S2P_TankVol_B_61 : 16|16@1+ (0.001,-30) [-30|35.535] "V"  PC
 SG_ S2P_TankVol_CalResult_61 : 32|2@1+ (1,0) [0|3] ""  PC

BO_ 2400513662 S2P_Detail_KB__62: 8 SBMU
 SG_ S2P_TankVol_K_62 : 0|16@1+ (0.001,0) [0|65.535] ""  PC
 SG_ S2P_TankVol_B_62 : 16|16@1+ (0.001,-30) [-30|35.535] "V"  PC
 SG_ S2P_TankVol_CalResult_62 : 32|2@1+ (1,0) [0|3] ""  PC

BO_ 2400513663 S2P_Detail_KB__63: 8 SBMU
 SG_ S2P_TankVol_K_63 : 0|16@1+ (0.001,0) [0|65.535] ""  PC
 SG_ S2P_TankVol_B_63 : 16|16@1+ (0.001,-30) [-30|35.535] "V"  PC
 SG_ S2P_TankVol_CalResult_63 : 32|2@1+ (1,0) [0|3] ""  PC

BO_ 2415980097 S2P_LEM_Meg__01: 8 SBMU
 SG_ IP_VALUE_01 : 7|32@1+ (1,-2147483648) [-2147483648|2147483647] "mA"  PC
 SG_ ERROR_INDICATION_01 : 39|1@1+ (1,0) [0|1] ""  PC
 SG_ ERROR_INFORMATION_01 : 40|7@1+ (1,0) [0|127] ""  PC
 SG_ VACANT_DATA_3BYTES_01 : 47|24@1+ (1,0) [0|16777215] ""  PC

BO_ 2415980098 S2P_LEM_Meg__02: 8 SBMU
 SG_ IP_VALUE_02 : 7|32@1+ (1,-2147483648) [-2147483648|2147483647] "mA"  PC
 SG_ ERROR_INDICATION_02 : 39|1@1+ (1,0) [0|1] ""  PC
 SG_ ERROR_INFORMATION_02 : 40|7@1+ (1,0) [0|127] ""  PC
 SG_ VACANT_DATA_3BYTES_02 : 47|24@1+ (1,0) [0|16777215] ""  PC

BO_ 2415980099 S2P_LEM_Meg__03: 8 SBMU
 SG_ IP_VALUE_03 : 7|32@1+ (1,-2147483648) [-2147483648|2147483647] "mA"  PC
 SG_ ERROR_INDICATION_03 : 39|1@1+ (1,0) [0|1] ""  PC
 SG_ ERROR_INFORMATION_03 : 40|7@1+ (1,0) [0|127] ""  PC
 SG_ VACANT_DATA_3BYTES_03 : 47|24@1+ (1,0) [0|16777215] ""  PC

BO_ 2415980100 S2P_LEM_Meg__04: 8 SBMU
 SG_ IP_VALUE_04 : 7|32@1+ (1,-2147483648) [-2147483648|2147483647] "mA"  PC
 SG_ ERROR_INDICATION_04 : 39|1@1+ (1,0) [0|1] ""  PC
 SG_ ERROR_INFORMATION_04 : 40|7@1+ (1,0) [0|127] ""  PC
 SG_ VACANT_DATA_3BYTES_04 : 47|24@1+ (1,0) [0|16777215] ""  PC

BO_ 2415980101 S2P_LEM_Meg__05: 8 SBMU
 SG_ IP_VALUE_05 : 7|32@1+ (1,-2147483648) [-2147483648|2147483647] "mA"  PC
 SG_ ERROR_INDICATION_05 : 39|1@1+ (1,0) [0|1] ""  PC
 SG_ ERROR_INFORMATION_05 : 40|7@1+ (1,0) [0|127] ""  PC
 SG_ VACANT_DATA_3BYTES_05 : 47|24@1+ (1,0) [0|16777215] ""  PC

BO_ 2415980102 S2P_LEM_Meg__06: 8 SBMU
 SG_ IP_VALUE_06 : 7|32@1+ (1,-2147483648) [-2147483648|2147483647] "mA"  PC
 SG_ ERROR_INDICATION_06 : 39|1@1+ (1,0) [0|1] ""  PC
 SG_ ERROR_INFORMATION_06 : 40|7@1+ (1,0) [0|127] ""  PC
 SG_ VACANT_DATA_3BYTES_06 : 47|24@1+ (1,0) [0|16777215] ""  PC

BO_ 2415980103 S2P_LEM_Meg__07: 8 SBMU
 SG_ IP_VALUE_07 : 7|32@1+ (1,-2147483648) [-2147483648|2147483647] "mA"  PC
 SG_ ERROR_INDICATION_07 : 39|1@1+ (1,0) [0|1] ""  PC
 SG_ ERROR_INFORMATION_07 : 40|7@1+ (1,0) [0|127] ""  PC
 SG_ VACANT_DATA_3BYTES_07 : 47|24@1+ (1,0) [0|16777215] ""  PC

BO_ 2415980104 S2P_LEM_Meg__08: 8 SBMU
 SG_ IP_VALUE_08 : 7|32@1+ (1,-2147483648) [-2147483648|2147483647] "mA"  PC
 SG_ ERROR_INDICATION_08 : 39|1@1+ (1,0) [0|1] ""  PC
 SG_ ERROR_INFORMATION_08 : 40|7@1+ (1,0) [0|127] ""  PC
 SG_ VACANT_DATA_3BYTES_08 : 47|24@1+ (1,0) [0|16777215] ""  PC

BO_ 2415980105 S2P_LEM_Meg__09: 8 SBMU
 SG_ IP_VALUE_09 : 7|32@1+ (1,-2147483648) [-2147483648|2147483647] "mA"  PC
 SG_ ERROR_INDICATION_09 : 39|1@1+ (1,0) [0|1] ""  PC
 SG_ ERROR_INFORMATION_09 : 40|7@1+ (1,0) [0|127] ""  PC
 SG_ VACANT_DATA_3BYTES_09 : 47|24@1+ (1,0) [0|16777215] ""  PC

BO_ 2415980106 S2P_LEM_Meg__10: 8 SBMU
 SG_ IP_VALUE_10 : 7|32@1+ (1,-2147483648) [-2147483648|2147483647] "mA"  PC
 SG_ ERROR_INDICATION_10 : 39|1@1+ (1,0) [0|1] ""  PC
 SG_ ERROR_INFORMATION_10 : 40|7@1+ (1,0) [0|127] ""  PC
 SG_ VACANT_DATA_3BYTES_10 : 47|24@1+ (1,0) [0|16777215] ""  PC

BO_ 2415980107 S2P_LEM_Meg__11: 8 SBMU
 SG_ IP_VALUE_11 : 7|32@1+ (1,-2147483648) [-2147483648|2147483647] "mA"  PC
 SG_ ERROR_INDICATION_11 : 39|1@1+ (1,0) [0|1] ""  PC
 SG_ ERROR_INFORMATION_11 : 40|7@1+ (1,0) [0|127] ""  PC
 SG_ VACANT_DATA_3BYTES_11 : 47|24@1+ (1,0) [0|16777215] ""  PC

BO_ 2415980108 S2P_LEM_Meg__12: 8 SBMU
 SG_ IP_VALUE_12 : 7|32@1+ (1,-2147483648) [-2147483648|2147483647] "mA"  PC
 SG_ ERROR_INDICATION_12 : 39|1@1+ (1,0) [0|1] ""  PC
 SG_ ERROR_INFORMATION_12 : 40|7@1+ (1,0) [0|127] ""  PC
 SG_ VACANT_DATA_3BYTES_12 : 47|24@1+ (1,0) [0|16777215] ""  PC

BO_ 2415980109 S2P_LEM_Meg__13: 8 SBMU
 SG_ IP_VALUE_13 : 7|32@1+ (1,-2147483648) [-2147483648|2147483647] "mA"  PC
 SG_ ERROR_INDICATION_13 : 39|1@1+ (1,0) [0|1] ""  PC
 SG_ ERROR_INFORMATION_13 : 40|7@1+ (1,0) [0|127] ""  PC
 SG_ VACANT_DATA_3BYTES_13 : 47|24@1+ (1,0) [0|16777215] ""  PC

BO_ 2415980110 S2P_LEM_Meg__14: 8 SBMU
 SG_ IP_VALUE_14 : 7|32@1+ (1,-2147483648) [-2147483648|2147483647] "mA"  PC
 SG_ ERROR_INDICATION_14 : 39|1@1+ (1,0) [0|1] ""  PC
 SG_ ERROR_INFORMATION_14 : 40|7@1+ (1,0) [0|127] ""  PC
 SG_ VACANT_DATA_3BYTES_14 : 47|24@1+ (1,0) [0|16777215] ""  PC

BO_ 2415980111 S2P_LEM_Meg__15: 8 SBMU
 SG_ IP_VALUE_15 : 7|32@1+ (1,-2147483648) [-2147483648|2147483647] "mA"  PC
 SG_ ERROR_INDICATION_15 : 39|1@1+ (1,0) [0|1] ""  PC
 SG_ ERROR_INFORMATION_15 : 40|7@1+ (1,0) [0|127] ""  PC
 SG_ VACANT_DATA_3BYTES_15 : 47|24@1+ (1,0) [0|16777215] ""  PC

BO_ 2415980112 S2P_LEM_Meg__16: 8 SBMU
 SG_ IP_VALUE_16 : 7|32@1+ (1,-2147483648) [-2147483648|2147483647] "mA"  PC
 SG_ ERROR_INDICATION_16 : 39|1@1+ (1,0) [0|1] ""  PC
 SG_ ERROR_INFORMATION_16 : 40|7@1+ (1,0) [0|127] ""  PC
 SG_ VACANT_DATA_3BYTES_16 : 47|24@1+ (1,0) [0|16777215] ""  PC

BO_ 2415980113 S2P_LEM_Meg__17: 8 SBMU
 SG_ IP_VALUE_17 : 7|32@1+ (1,-2147483648) [-2147483648|2147483647] "mA"  PC
 SG_ ERROR_INDICATION_17 : 39|1@1+ (1,0) [0|1] ""  PC
 SG_ ERROR_INFORMATION_17 : 40|7@1+ (1,0) [0|127] ""  PC
 SG_ VACANT_DATA_3BYTES_17 : 47|24@1+ (1,0) [0|16777215] ""  PC

BO_ 2415980114 S2P_LEM_Meg__18: 8 SBMU
 SG_ IP_VALUE_18 : 7|32@1+ (1,-2147483648) [-2147483648|2147483647] "mA"  PC
 SG_ ERROR_INDICATION_18 : 39|1@1+ (1,0) [0|1] ""  PC
 SG_ ERROR_INFORMATION_18 : 40|7@1+ (1,0) [0|127] ""  PC
 SG_ VACANT_DATA_3BYTES_18 : 47|24@1+ (1,0) [0|16777215] ""  PC

BO_ 2415980115 S2P_LEM_Meg__19: 8 SBMU
 SG_ IP_VALUE_19 : 7|32@1+ (1,-2147483648) [-2147483648|2147483647] "mA"  PC
 SG_ ERROR_INDICATION_19 : 39|1@1+ (1,0) [0|1] ""  PC
 SG_ ERROR_INFORMATION_19 : 40|7@1+ (1,0) [0|127] ""  PC
 SG_ VACANT_DATA_3BYTES_19 : 47|24@1+ (1,0) [0|16777215] ""  PC

BO_ 2415980116 S2P_LEM_Meg__20: 8 SBMU
 SG_ IP_VALUE_20 : 7|32@1+ (1,-2147483648) [-2147483648|2147483647] "mA"  PC
 SG_ ERROR_INDICATION_20 : 39|1@1+ (1,0) [0|1] ""  PC
 SG_ ERROR_INFORMATION_20 : 40|7@1+ (1,0) [0|127] ""  PC
 SG_ VACANT_DATA_3BYTES_20 : 47|24@1+ (1,0) [0|16777215] ""  PC

BO_ 2415980117 S2P_LEM_Meg__21: 8 SBMU
 SG_ IP_VALUE_21 : 7|32@1+ (1,-2147483648) [-2147483648|2147483647] "mA"  PC
 SG_ ERROR_INDICATION_21 : 39|1@1+ (1,0) [0|1] ""  PC
 SG_ ERROR_INFORMATION_21 : 40|7@1+ (1,0) [0|127] ""  PC
 SG_ VACANT_DATA_3BYTES_21 : 47|24@1+ (1,0) [0|16777215] ""  PC

BO_ 2415980118 S2P_LEM_Meg__22: 8 SBMU
 SG_ IP_VALUE_22 : 7|32@1+ (1,-2147483648) [-2147483648|2147483647] "mA"  PC
 SG_ ERROR_INDICATION_22 : 39|1@1+ (1,0) [0|1] ""  PC
 SG_ ERROR_INFORMATION_22 : 40|7@1+ (1,0) [0|127] ""  PC
 SG_ VACANT_DATA_3BYTES_22 : 47|24@1+ (1,0) [0|16777215] ""  PC

BO_ 2415980119 S2P_LEM_Meg__23: 8 SBMU
 SG_ IP_VALUE_23 : 7|32@1+ (1,-2147483648) [-2147483648|2147483647] "mA"  PC
 SG_ ERROR_INDICATION_23 : 39|1@1+ (1,0) [0|1] ""  PC
 SG_ ERROR_INFORMATION_23 : 40|7@1+ (1,0) [0|127] ""  PC
 SG_ VACANT_DATA_3BYTES_23 : 47|24@1+ (1,0) [0|16777215] ""  PC

BO_ 2415980120 S2P_LEM_Meg__24: 8 SBMU
 SG_ IP_VALUE_24 : 7|32@1+ (1,-2147483648) [-2147483648|2147483647] "mA"  PC
 SG_ ERROR_INDICATION_24 : 39|1@1+ (1,0) [0|1] ""  PC
 SG_ ERROR_INFORMATION_24 : 40|7@1+ (1,0) [0|127] ""  PC
 SG_ VACANT_DATA_3BYTES_24 : 47|24@1+ (1,0) [0|16777215] ""  PC

BO_ 2415980121 S2P_LEM_Meg__25: 8 SBMU
 SG_ IP_VALUE_25 : 7|32@1+ (1,-2147483648) [-2147483648|2147483647] "mA"  PC
 SG_ ERROR_INDICATION_25 : 39|1@1+ (1,0) [0|1] ""  PC
 SG_ ERROR_INFORMATION_25 : 40|7@1+ (1,0) [0|127] ""  PC
 SG_ VACANT_DATA_3BYTES_25 : 47|24@1+ (1,0) [0|16777215] ""  PC

BO_ 2415980122 S2P_LEM_Meg__26: 8 SBMU
 SG_ IP_VALUE_26 : 7|32@1+ (1,-2147483648) [-2147483648|2147483647] "mA"  PC
 SG_ ERROR_INDICATION_26 : 39|1@1+ (1,0) [0|1] ""  PC
 SG_ ERROR_INFORMATION_26 : 40|7@1+ (1,0) [0|127] ""  PC
 SG_ VACANT_DATA_3BYTES_26 : 47|24@1+ (1,0) [0|16777215] ""  PC

BO_ 2415980123 S2P_LEM_Meg__27: 8 SBMU
 SG_ IP_VALUE_27 : 7|32@1+ (1,-2147483648) [-2147483648|2147483647] "mA"  PC
 SG_ ERROR_INDICATION_27 : 39|1@1+ (1,0) [0|1] ""  PC
 SG_ ERROR_INFORMATION_27 : 40|7@1+ (1,0) [0|127] ""  PC
 SG_ VACANT_DATA_3BYTES_27 : 47|24@1+ (1,0) [0|16777215] ""  PC

BO_ 2415980124 S2P_LEM_Meg__28: 8 SBMU
 SG_ IP_VALUE_28 : 7|32@1+ (1,-2147483648) [-2147483648|2147483647] "mA"  PC
 SG_ ERROR_INDICATION_28 : 39|1@1+ (1,0) [0|1] ""  PC
 SG_ ERROR_INFORMATION_28 : 40|7@1+ (1,0) [0|127] ""  PC
 SG_ VACANT_DATA_3BYTES_28 : 47|24@1+ (1,0) [0|16777215] ""  PC

BO_ 2415980125 S2P_LEM_Meg__29: 8 SBMU
 SG_ IP_VALUE_29 : 7|32@1+ (1,-2147483648) [-2147483648|2147483647] "mA"  PC
 SG_ ERROR_INDICATION_29 : 39|1@1+ (1,0) [0|1] ""  PC
 SG_ ERROR_INFORMATION_29 : 40|7@1+ (1,0) [0|127] ""  PC
 SG_ VACANT_DATA_3BYTES_29 : 47|24@1+ (1,0) [0|16777215] ""  PC

BO_ 2415980126 S2P_LEM_Meg__30: 8 SBMU
 SG_ IP_VALUE_30 : 7|32@1+ (1,-2147483648) [-2147483648|2147483647] "mA"  PC
 SG_ ERROR_INDICATION_30 : 39|1@1+ (1,0) [0|1] ""  PC
 SG_ ERROR_INFORMATION_30 : 40|7@1+ (1,0) [0|127] ""  PC
 SG_ VACANT_DATA_3BYTES_30 : 47|24@1+ (1,0) [0|16777215] ""  PC

BO_ 2415980127 S2P_LEM_Meg__31: 8 SBMU
 SG_ IP_VALUE_31 : 7|32@1+ (1,-2147483648) [-2147483648|2147483647] "mA"  PC
 SG_ ERROR_INDICATION_31 : 39|1@1+ (1,0) [0|1] ""  PC
 SG_ ERROR_INFORMATION_31 : 40|7@1+ (1,0) [0|127] ""  PC
 SG_ VACANT_DATA_3BYTES_31 : 47|24@1+ (1,0) [0|16777215] ""  PC

BO_ 2415980128 S2P_LEM_Meg__32: 8 SBMU
 SG_ IP_VALUE_32 : 7|32@1+ (1,-2147483648) [-2147483648|2147483647] "mA"  PC
 SG_ ERROR_INDICATION_32 : 39|1@1+ (1,0) [0|1] ""  PC
 SG_ ERROR_INFORMATION_32 : 40|7@1+ (1,0) [0|127] ""  PC
 SG_ VACANT_DATA_3BYTES_32 : 47|24@1+ (1,0) [0|16777215] ""  PC

BO_ 2415980129 S2P_LEM_Meg__33: 8 SBMU
 SG_ IP_VALUE_33 : 7|32@1+ (1,-2147483648) [-2147483648|2147483647] "mA"  PC
 SG_ ERROR_INDICATION_33 : 39|1@1+ (1,0) [0|1] ""  PC
 SG_ ERROR_INFORMATION_33 : 40|7@1+ (1,0) [0|127] ""  PC
 SG_ VACANT_DATA_3BYTES_33 : 47|24@1+ (1,0) [0|16777215] ""  PC

BO_ 2415980130 S2P_LEM_Meg__34: 8 SBMU
 SG_ IP_VALUE_34 : 7|32@1+ (1,-2147483648) [-2147483648|2147483647] "mA"  PC
 SG_ ERROR_INDICATION_34 : 39|1@1+ (1,0) [0|1] ""  PC
 SG_ ERROR_INFORMATION_34 : 40|7@1+ (1,0) [0|127] ""  PC
 SG_ VACANT_DATA_3BYTES_34 : 47|24@1+ (1,0) [0|16777215] ""  PC

BO_ 2415980131 S2P_LEM_Meg__35: 8 SBMU
 SG_ IP_VALUE_35 : 7|32@1+ (1,-2147483648) [-2147483648|2147483647] "mA"  PC
 SG_ ERROR_INDICATION_35 : 39|1@1+ (1,0) [0|1] ""  PC
 SG_ ERROR_INFORMATION_35 : 40|7@1+ (1,0) [0|127] ""  PC
 SG_ VACANT_DATA_3BYTES_35 : 47|24@1+ (1,0) [0|16777215] ""  PC

BO_ 2415980132 S2P_LEM_Meg__36: 8 SBMU
 SG_ IP_VALUE_36 : 7|32@1+ (1,-2147483648) [-2147483648|2147483647] "mA"  PC
 SG_ ERROR_INDICATION_36 : 39|1@1+ (1,0) [0|1] ""  PC
 SG_ ERROR_INFORMATION_36 : 40|7@1+ (1,0) [0|127] ""  PC
 SG_ VACANT_DATA_3BYTES_36 : 47|24@1+ (1,0) [0|16777215] ""  PC

BO_ 2415980133 S2P_LEM_Meg__37: 8 SBMU
 SG_ IP_VALUE_37 : 7|32@1+ (1,-2147483648) [-2147483648|2147483647] "mA"  PC
 SG_ ERROR_INDICATION_37 : 39|1@1+ (1,0) [0|1] ""  PC
 SG_ ERROR_INFORMATION_37 : 40|7@1+ (1,0) [0|127] ""  PC
 SG_ VACANT_DATA_3BYTES_37 : 47|24@1+ (1,0) [0|16777215] ""  PC

BO_ 2415980134 S2P_LEM_Meg__38: 8 SBMU
 SG_ IP_VALUE_38 : 7|32@1+ (1,-2147483648) [-2147483648|2147483647] "mA"  PC
 SG_ ERROR_INDICATION_38 : 39|1@1+ (1,0) [0|1] ""  PC
 SG_ ERROR_INFORMATION_38 : 40|7@1+ (1,0) [0|127] ""  PC
 SG_ VACANT_DATA_3BYTES_38 : 47|24@1+ (1,0) [0|16777215] ""  PC

BO_ 2415980135 S2P_LEM_Meg__39: 8 SBMU
 SG_ IP_VALUE_39 : 7|32@1+ (1,-2147483648) [-2147483648|2147483647] "mA"  PC
 SG_ ERROR_INDICATION_39 : 39|1@1+ (1,0) [0|1] ""  PC
 SG_ ERROR_INFORMATION_39 : 40|7@1+ (1,0) [0|127] ""  PC
 SG_ VACANT_DATA_3BYTES_39 : 47|24@1+ (1,0) [0|16777215] ""  PC

BO_ 2415980136 S2P_LEM_Meg__40: 8 SBMU
 SG_ IP_VALUE_40 : 7|32@1+ (1,-2147483648) [-2147483648|2147483647] "mA"  PC
 SG_ ERROR_INDICATION_40 : 39|1@1+ (1,0) [0|1] ""  PC
 SG_ ERROR_INFORMATION_40 : 40|7@1+ (1,0) [0|127] ""  PC
 SG_ VACANT_DATA_3BYTES_40 : 47|24@1+ (1,0) [0|16777215] ""  PC

BO_ 2415980137 S2P_LEM_Meg__41: 8 SBMU
 SG_ IP_VALUE_41 : 7|32@1+ (1,-2147483648) [-2147483648|2147483647] "mA"  PC
 SG_ ERROR_INDICATION_41 : 39|1@1+ (1,0) [0|1] ""  PC
 SG_ ERROR_INFORMATION_41 : 40|7@1+ (1,0) [0|127] ""  PC
 SG_ VACANT_DATA_3BYTES_41 : 47|24@1+ (1,0) [0|16777215] ""  PC

BO_ 2415980138 S2P_LEM_Meg__42: 8 SBMU
 SG_ IP_VALUE_42 : 7|32@1+ (1,-2147483648) [-2147483648|2147483647] "mA"  PC
 SG_ ERROR_INDICATION_42 : 39|1@1+ (1,0) [0|1] ""  PC
 SG_ ERROR_INFORMATION_42 : 40|7@1+ (1,0) [0|127] ""  PC
 SG_ VACANT_DATA_3BYTES_42 : 47|24@1+ (1,0) [0|16777215] ""  PC

BO_ 2415980139 S2P_LEM_Meg__43: 8 SBMU
 SG_ IP_VALUE_43 : 7|32@1+ (1,-2147483648) [-2147483648|2147483647] "mA"  PC
 SG_ ERROR_INDICATION_43 : 39|1@1+ (1,0) [0|1] ""  PC
 SG_ ERROR_INFORMATION_43 : 40|7@1+ (1,0) [0|127] ""  PC
 SG_ VACANT_DATA_3BYTES_43 : 47|24@1+ (1,0) [0|16777215] ""  PC

BO_ 2415980140 S2P_LEM_Meg__44: 8 SBMU
 SG_ IP_VALUE_44 : 7|32@1+ (1,-2147483648) [-2147483648|2147483647] "mA"  PC
 SG_ ERROR_INDICATION_44 : 39|1@1+ (1,0) [0|1] ""  PC
 SG_ ERROR_INFORMATION_44 : 40|7@1+ (1,0) [0|127] ""  PC
 SG_ VACANT_DATA_3BYTES_44 : 47|24@1+ (1,0) [0|16777215] ""  PC

BO_ 2415980141 S2P_LEM_Meg__45: 8 SBMU
 SG_ IP_VALUE_45 : 7|32@1+ (1,-2147483648) [-2147483648|2147483647] "mA"  PC
 SG_ ERROR_INDICATION_45 : 39|1@1+ (1,0) [0|1] ""  PC
 SG_ ERROR_INFORMATION_45 : 40|7@1+ (1,0) [0|127] ""  PC
 SG_ VACANT_DATA_3BYTES_45 : 47|24@1+ (1,0) [0|16777215] ""  PC

BO_ 2415980142 S2P_LEM_Meg__46: 8 SBMU
 SG_ IP_VALUE_46 : 7|32@1+ (1,-2147483648) [-2147483648|2147483647] "mA"  PC
 SG_ ERROR_INDICATION_46 : 39|1@1+ (1,0) [0|1] ""  PC
 SG_ ERROR_INFORMATION_46 : 40|7@1+ (1,0) [0|127] ""  PC
 SG_ VACANT_DATA_3BYTES_46 : 47|24@1+ (1,0) [0|16777215] ""  PC

BO_ 2415980143 S2P_LEM_Meg__47: 8 SBMU
 SG_ IP_VALUE_47 : 7|32@1+ (1,-2147483648) [-2147483648|2147483647] "mA"  PC
 SG_ ERROR_INDICATION_47 : 39|1@1+ (1,0) [0|1] ""  PC
 SG_ ERROR_INFORMATION_47 : 40|7@1+ (1,0) [0|127] ""  PC
 SG_ VACANT_DATA_3BYTES_47 : 47|24@1+ (1,0) [0|16777215] ""  PC

BO_ 2415980144 S2P_LEM_Meg__48: 8 SBMU
 SG_ IP_VALUE_48 : 7|32@1+ (1,-2147483648) [-2147483648|2147483647] "mA"  PC
 SG_ ERROR_INDICATION_48 : 39|1@1+ (1,0) [0|1] ""  PC
 SG_ ERROR_INFORMATION_48 : 40|7@1+ (1,0) [0|127] ""  PC
 SG_ VACANT_DATA_3BYTES_48 : 47|24@1+ (1,0) [0|16777215] ""  PC

BO_ 2415980145 S2P_LEM_Meg__49: 8 SBMU
 SG_ IP_VALUE_49 : 7|32@1+ (1,-2147483648) [-2147483648|2147483647] "mA"  PC
 SG_ ERROR_INDICATION_49 : 39|1@1+ (1,0) [0|1] ""  PC
 SG_ ERROR_INFORMATION_49 : 40|7@1+ (1,0) [0|127] ""  PC
 SG_ VACANT_DATA_3BYTES_49 : 47|24@1+ (1,0) [0|16777215] ""  PC

BO_ 2415980146 S2P_LEM_Meg__50: 8 SBMU
 SG_ IP_VALUE_50 : 7|32@1+ (1,-2147483648) [-2147483648|2147483647] "mA"  PC
 SG_ ERROR_INDICATION_50 : 39|1@1+ (1,0) [0|1] ""  PC
 SG_ ERROR_INFORMATION_50 : 40|7@1+ (1,0) [0|127] ""  PC
 SG_ VACANT_DATA_3BYTES_50 : 47|24@1+ (1,0) [0|16777215] ""  PC

BO_ 2415980147 S2P_LEM_Meg__51: 8 SBMU
 SG_ IP_VALUE_51 : 7|32@1+ (1,-2147483648) [-2147483648|2147483647] "mA"  PC
 SG_ ERROR_INDICATION_51 : 39|1@1+ (1,0) [0|1] ""  PC
 SG_ ERROR_INFORMATION_51 : 40|7@1+ (1,0) [0|127] ""  PC
 SG_ VACANT_DATA_3BYTES_51 : 47|24@1+ (1,0) [0|16777215] ""  PC

BO_ 2415980148 S2P_LEM_Meg__52: 8 SBMU
 SG_ IP_VALUE_52 : 7|32@1+ (1,-2147483648) [-2147483648|2147483647] "mA"  PC
 SG_ ERROR_INDICATION_52 : 39|1@1+ (1,0) [0|1] ""  PC
 SG_ ERROR_INFORMATION_52 : 40|7@1+ (1,0) [0|127] ""  PC
 SG_ VACANT_DATA_3BYTES_52 : 47|24@1+ (1,0) [0|16777215] ""  PC

BO_ 2415980149 S2P_LEM_Meg__53: 8 SBMU
 SG_ IP_VALUE_53 : 7|32@1+ (1,-2147483648) [-2147483648|2147483647] "mA"  PC
 SG_ ERROR_INDICATION_53 : 39|1@1+ (1,0) [0|1] ""  PC
 SG_ ERROR_INFORMATION_53 : 40|7@1+ (1,0) [0|127] ""  PC
 SG_ VACANT_DATA_3BYTES_53 : 47|24@1+ (1,0) [0|16777215] ""  PC

BO_ 2415980150 S2P_LEM_Meg__54: 8 SBMU
 SG_ IP_VALUE_54 : 7|32@1+ (1,-2147483648) [-2147483648|2147483647] "mA"  PC
 SG_ ERROR_INDICATION_54 : 39|1@1+ (1,0) [0|1] ""  PC
 SG_ ERROR_INFORMATION_54 : 40|7@1+ (1,0) [0|127] ""  PC
 SG_ VACANT_DATA_3BYTES_54 : 47|24@1+ (1,0) [0|16777215] ""  PC

BO_ 2415980151 S2P_LEM_Meg__55: 8 SBMU
 SG_ IP_VALUE_55 : 7|32@1+ (1,-2147483648) [-2147483648|2147483647] "mA"  PC
 SG_ ERROR_INDICATION_55 : 39|1@1+ (1,0) [0|1] ""  PC
 SG_ ERROR_INFORMATION_55 : 40|7@1+ (1,0) [0|127] ""  PC
 SG_ VACANT_DATA_3BYTES_55 : 47|24@1+ (1,0) [0|16777215] ""  PC

BO_ 2415980152 S2P_LEM_Meg__56: 8 SBMU
 SG_ IP_VALUE_56 : 7|32@1+ (1,-2147483648) [-2147483648|2147483647] "mA"  PC
 SG_ ERROR_INDICATION_56 : 39|1@1+ (1,0) [0|1] ""  PC
 SG_ ERROR_INFORMATION_56 : 40|7@1+ (1,0) [0|127] ""  PC
 SG_ VACANT_DATA_3BYTES_56 : 47|24@1+ (1,0) [0|16777215] ""  PC

BO_ 2415980153 S2P_LEM_Meg__57: 8 SBMU
 SG_ IP_VALUE_57 : 7|32@1+ (1,-2147483648) [-2147483648|2147483647] "mA"  PC
 SG_ ERROR_INDICATION_57 : 39|1@1+ (1,0) [0|1] ""  PC
 SG_ ERROR_INFORMATION_57 : 40|7@1+ (1,0) [0|127] ""  PC
 SG_ VACANT_DATA_3BYTES_57 : 47|24@1+ (1,0) [0|16777215] ""  PC

BO_ 2415980154 S2P_LEM_Meg__58: 8 SBMU
 SG_ IP_VALUE_58 : 7|32@1+ (1,-2147483648) [-2147483648|2147483647] "mA"  PC
 SG_ ERROR_INDICATION_58 : 39|1@1+ (1,0) [0|1] ""  PC
 SG_ ERROR_INFORMATION_58 : 40|7@1+ (1,0) [0|127] ""  PC
 SG_ VACANT_DATA_3BYTES_58 : 47|24@1+ (1,0) [0|16777215] ""  PC

BO_ 2415980155 S2P_LEM_Meg__59: 8 SBMU
 SG_ IP_VALUE_59 : 7|32@1+ (1,-2147483648) [-2147483648|2147483647] "mA"  PC
 SG_ ERROR_INDICATION_59 : 39|1@1+ (1,0) [0|1] ""  PC
 SG_ ERROR_INFORMATION_59 : 40|7@1+ (1,0) [0|127] ""  PC
 SG_ VACANT_DATA_3BYTES_59 : 47|24@1+ (1,0) [0|16777215] ""  PC

BO_ 2415980156 S2P_LEM_Meg__60: 8 SBMU
 SG_ IP_VALUE_60 : 7|32@1+ (1,-2147483648) [-2147483648|2147483647] "mA"  PC
 SG_ ERROR_INDICATION_60 : 39|1@1+ (1,0) [0|1] ""  PC
 SG_ ERROR_INFORMATION_60 : 40|7@1+ (1,0) [0|127] ""  PC
 SG_ VACANT_DATA_3BYTES_60 : 47|24@1+ (1,0) [0|16777215] ""  PC

BO_ 2415980157 S2P_LEM_Meg__61: 8 SBMU
 SG_ IP_VALUE_61 : 7|32@1+ (1,-2147483648) [-2147483648|2147483647] "mA"  PC
 SG_ ERROR_INDICATION_61 : 39|1@1+ (1,0) [0|1] ""  PC
 SG_ ERROR_INFORMATION_61 : 40|7@1+ (1,0) [0|127] ""  PC
 SG_ VACANT_DATA_3BYTES_61 : 47|24@1+ (1,0) [0|16777215] ""  PC

BO_ 2415980158 S2P_LEM_Meg__62: 8 SBMU
 SG_ IP_VALUE_62 : 7|32@1+ (1,-2147483648) [-2147483648|2147483647] "mA"  PC
 SG_ ERROR_INDICATION_62 : 39|1@1+ (1,0) [0|1] ""  PC
 SG_ ERROR_INFORMATION_62 : 40|7@1+ (1,0) [0|127] ""  PC
 SG_ VACANT_DATA_3BYTES_62 : 47|24@1+ (1,0) [0|16777215] ""  PC

BO_ 2415980159 S2P_LEM_Meg__63: 8 SBMU
 SG_ IP_VALUE_63 : 7|32@1+ (1,-2147483648) [-2147483648|2147483647] "mA"  PC
 SG_ ERROR_INDICATION_63 : 39|1@1+ (1,0) [0|1] ""  PC
 SG_ ERROR_INFORMATION_63 : 40|7@1+ (1,0) [0|127] ""  PC
 SG_ VACANT_DATA_3BYTES_63 : 47|24@1+ (1,0) [0|16777215] ""  PC

BO_ 2417487425 S2P_BL_Meg__01: 8 SBMU
 SG_ S2P_Bal_CSCNum_01 : 0|6@1+ (1,0) [0|63] ""  PC
 SG_ S2P_Bal_CellNum_01 : 6|6@1+ (1,0) [0|63] ""  PC
 SG_ S2P_Bal_Type_01 : 12|2@1+ (1,0) [0|3] ""  PC
 SG_ S2P_Bal_TimeRemain_01 : 14|9@1+ (1,0) [0|511] ""  PC
 SG_ S2P_Bal_DeltaVolt_01 : 23|10@1+ (1,0) [0|1023] ""  PC
 SG_ S2P_Bal_CSCPowerCurr_01 : 33|11@1+ (1,0) [0|2047] ""  PC
 SG_ S2P_Bal_TypeLevel_01 : 44|3@1+ (1,0) [0|7] ""  PC
 SG_ S2P_Bal_SystemStatus_01 : 47|2@1+ (1,0) [0|3] ""  PC
 SG_ S2P_Bal_Strategy_01 : 49|1@1+ (1,0) [0|1] ""  PC
 SG_ S2P_Bal_ForceBalMode_01 : 50|2@1+ (1,0) [0|3] ""  PC
 SG_ S2P_Bal_CellTempFault_01 : 52|1@1+ (1,0) [0|1] ""  PC
 SG_ S2P_Bal_CellVoltFail_01 : 53|1@1+ (1,0) [0|1] ""  PC
 SG_ S2P_Bal_CloseBalInstruct_01 : 54|1@1+ (1,0) [0|1] ""  PC
 SG_ S2P_Bal_CCanTimeOut_01 : 55|1@1+ (1,0) [0|1] ""  PC
 SG_ S2P_Bal_CellOffLine_01 : 56|1@1+ (1,0) [0|1] ""  PC
 SG_ S2P_Bal_BalanceCircuitFault_01 : 57|1@1+ (1,0) [0|1] ""  PC
 SG_ S2P_Bal_CSCSourceVoltFault_01 : 58|1@1+ (1,0) [0|1] ""  PC
 SG_ S2P_Bal_CellVoltOverFault_01 : 59|1@1+ (1,0) [0|1] ""  PC
 SG_ S2P_Bal_CellVoltLowFault_01 : 60|1@1+ (1,0) [0|1] ""  PC
 SG_ S2P_Bal_CSCPCBTempFault_01 : 61|1@1+ (1,0) [0|1] ""  PC
 SG_ S2P_Bal_CSCSourceCurrLowFault_01 : 62|1@1+ (1,0) [0|1] ""  PC
 SG_ S2P_Bal_CSCSourceCurrOvrFault_01 : 63|1@1+ (1,0) [0|1] ""  PC

BO_ 2417487426 S2P_BL_Meg__02: 8 SBMU
 SG_ S2P_Bal_CSCNum_02 : 0|6@1+ (1,0) [0|63] ""  PC
 SG_ S2P_Bal_CellNum_02 : 6|6@1+ (1,0) [0|63] ""  PC
 SG_ S2P_Bal_Type_02 : 12|2@1+ (1,0) [0|3] ""  PC
 SG_ S2P_Bal_TimeRemain_02 : 14|9@1+ (1,0) [0|511] ""  PC
 SG_ S2P_Bal_DeltaVolt_02 : 23|10@1+ (1,0) [0|1023] ""  PC
 SG_ S2P_Bal_CSCPowerCurr_02 : 33|11@1+ (1,0) [0|2047] ""  PC
 SG_ S2P_Bal_TypeLevel_02 : 44|3@1+ (1,0) [0|7] ""  PC
 SG_ S2P_Bal_SystemStatus_02 : 47|2@1+ (1,0) [0|3] ""  PC
 SG_ S2P_Bal_Strategy_02 : 49|1@1+ (1,0) [0|1] ""  PC
 SG_ S2P_Bal_ForceBalMode_02 : 50|2@1+ (1,0) [0|3] ""  PC
 SG_ S2P_Bal_CellTempFault_02 : 52|1@1+ (1,0) [0|1] ""  PC
 SG_ S2P_Bal_CellVoltFail_02 : 53|1@1+ (1,0) [0|1] ""  PC
 SG_ S2P_Bal_CloseBalInstruct_02 : 54|1@1+ (1,0) [0|1] ""  PC
 SG_ S2P_Bal_CCanTimeOut_02 : 55|1@1+ (1,0) [0|1] ""  PC
 SG_ S2P_Bal_CellOffLine_02 : 56|1@1+ (1,0) [0|1] ""  PC
 SG_ S2P_Bal_BalanceCircuitFault_02 : 57|1@1+ (1,0) [0|1] ""  PC
 SG_ S2P_Bal_CSCSourceVoltFault_02 : 58|1@1+ (1,0) [0|1] ""  PC
 SG_ S2P_Bal_CellVoltOverFault_02 : 59|1@1+ (1,0) [0|1] ""  PC
 SG_ S2P_Bal_CellVoltLowFault_02 : 60|1@1+ (1,0) [0|1] ""  PC
 SG_ S2P_Bal_CSCPCBTempFault_02 : 61|1@1+ (1,0) [0|1] ""  PC
 SG_ S2P_Bal_CSCSourceCurrLowFault_02 : 62|1@1+ (1,0) [0|1] ""  PC
 SG_ S2P_Bal_CSCSourceCurrOvrFault_02 : 63|1@1+ (1,0) [0|1] ""  PC

BO_ 2417487427 S2P_BL_Meg__03: 8 SBMU
 SG_ S2P_Bal_CSCNum_03 : 0|6@1+ (1,0) [0|63] ""  PC
 SG_ S2P_Bal_CellNum_03 : 6|6@1+ (1,0) [0|63] ""  PC
 SG_ S2P_Bal_Type_03 : 12|2@1+ (1,0) [0|3] ""  PC
 SG_ S2P_Bal_TimeRemain_03 : 14|9@1+ (1,0) [0|511] ""  PC
 SG_ S2P_Bal_DeltaVolt_03 : 23|10@1+ (1,0) [0|1023] ""  PC
 SG_ S2P_Bal_CSCPowerCurr_03 : 33|11@1+ (1,0) [0|2047] ""  PC
 SG_ S2P_Bal_TypeLevel_03 : 44|3@1+ (1,0) [0|7] ""  PC
 SG_ S2P_Bal_SystemStatus_03 : 47|2@1+ (1,0) [0|3] ""  PC
 SG_ S2P_Bal_Strategy_03 : 49|1@1+ (1,0) [0|1] ""  PC
 SG_ S2P_Bal_ForceBalMode_03 : 50|2@1+ (1,0) [0|3] ""  PC
 SG_ S2P_Bal_CellTempFault_03 : 52|1@1+ (1,0) [0|1] ""  PC
 SG_ S2P_Bal_CellVoltFail_03 : 53|1@1+ (1,0) [0|1] ""  PC
 SG_ S2P_Bal_CloseBalInstruct_03 : 54|1@1+ (1,0) [0|1] ""  PC
 SG_ S2P_Bal_CCanTimeOut_03 : 55|1@1+ (1,0) [0|1] ""  PC
 SG_ S2P_Bal_CellOffLine_03 : 56|1@1+ (1,0) [0|1] ""  PC
 SG_ S2P_Bal_BalanceCircuitFault_03 : 57|1@1+ (1,0) [0|1] ""  PC
 SG_ S2P_Bal_CSCSourceVoltFault_03 : 58|1@1+ (1,0) [0|1] ""  PC
 SG_ S2P_Bal_CellVoltOverFault_03 : 59|1@1+ (1,0) [0|1] ""  PC
 SG_ S2P_Bal_CellVoltLowFault_03 : 60|1@1+ (1,0) [0|1] ""  PC
 SG_ S2P_Bal_CSCPCBTempFault_03 : 61|1@1+ (1,0) [0|1] ""  PC
 SG_ S2P_Bal_CSCSourceCurrLowFault_03 : 62|1@1+ (1,0) [0|1] ""  PC
 SG_ S2P_Bal_CSCSourceCurrOvrFault_03 : 63|1@1+ (1,0) [0|1] ""  PC

BO_ 2417487428 S2P_BL_Meg__04: 8 SBMU
 SG_ S2P_Bal_CSCNum_04 : 0|6@1+ (1,0) [0|63] ""  PC
 SG_ S2P_Bal_CellNum_04 : 6|6@1+ (1,0) [0|63] ""  PC
 SG_ S2P_Bal_Type_04 : 12|2@1+ (1,0) [0|3] ""  PC
 SG_ S2P_Bal_TimeRemain_04 : 14|9@1+ (1,0) [0|511] ""  PC
 SG_ S2P_Bal_DeltaVolt_04 : 23|10@1+ (1,0) [0|1023] ""  PC
 SG_ S2P_Bal_CSCPowerCurr_04 : 33|11@1+ (1,0) [0|2047] ""  PC
 SG_ S2P_Bal_TypeLevel_04 : 44|3@1+ (1,0) [0|7] ""  PC
 SG_ S2P_Bal_SystemStatus_04 : 47|2@1+ (1,0) [0|3] ""  PC
 SG_ S2P_Bal_Strategy_04 : 49|1@1+ (1,0) [0|1] ""  PC
 SG_ S2P_Bal_ForceBalMode_04 : 50|2@1+ (1,0) [0|3] ""  PC
 SG_ S2P_Bal_CellTempFault_04 : 52|1@1+ (1,0) [0|1] ""  PC
 SG_ S2P_Bal_CellVoltFail_04 : 53|1@1+ (1,0) [0|1] ""  PC
 SG_ S2P_Bal_CloseBalInstruct_04 : 54|1@1+ (1,0) [0|1] ""  PC
 SG_ S2P_Bal_CCanTimeOut_04 : 55|1@1+ (1,0) [0|1] ""  PC
 SG_ S2P_Bal_CellOffLine_04 : 56|1@1+ (1,0) [0|1] ""  PC
 SG_ S2P_Bal_BalanceCircuitFault_04 : 57|1@1+ (1,0) [0|1] ""  PC
 SG_ S2P_Bal_CSCSourceVoltFault_04 : 58|1@1+ (1,0) [0|1] ""  PC
 SG_ S2P_Bal_CellVoltOverFault_04 : 59|1@1+ (1,0) [0|1] ""  PC
 SG_ S2P_Bal_CellVoltLowFault_04 : 60|1@1+ (1,0) [0|1] ""  PC
 SG_ S2P_Bal_CSCPCBTempFault_04 : 61|1@1+ (1,0) [0|1] ""  PC
 SG_ S2P_Bal_CSCSourceCurrLowFault_04 : 62|1@1+ (1,0) [0|1] ""  PC
 SG_ S2P_Bal_CSCSourceCurrOvrFault_04 : 63|1@1+ (1,0) [0|1] ""  PC

BO_ 2417487429 S2P_BL_Meg__05: 8 SBMU
 SG_ S2P_Bal_CSCNum_05 : 0|6@1+ (1,0) [0|63] ""  PC
 SG_ S2P_Bal_CellNum_05 : 6|6@1+ (1,0) [0|63] ""  PC
 SG_ S2P_Bal_Type_05 : 12|2@1+ (1,0) [0|3] ""  PC
 SG_ S2P_Bal_TimeRemain_05 : 14|9@1+ (1,0) [0|511] ""  PC
 SG_ S2P_Bal_DeltaVolt_05 : 23|10@1+ (1,0) [0|1023] ""  PC
 SG_ S2P_Bal_CSCPowerCurr_05 : 33|11@1+ (1,0) [0|2047] ""  PC
 SG_ S2P_Bal_TypeLevel_05 : 44|3@1+ (1,0) [0|7] ""  PC
 SG_ S2P_Bal_SystemStatus_05 : 47|2@1+ (1,0) [0|3] ""  PC
 SG_ S2P_Bal_Strategy_05 : 49|1@1+ (1,0) [0|1] ""  PC
 SG_ S2P_Bal_ForceBalMode_05 : 50|2@1+ (1,0) [0|3] ""  PC
 SG_ S2P_Bal_CellTempFault_05 : 52|1@1+ (1,0) [0|1] ""  PC
 SG_ S2P_Bal_CellVoltFail_05 : 53|1@1+ (1,0) [0|1] ""  PC
 SG_ S2P_Bal_CloseBalInstruct_05 : 54|1@1+ (1,0) [0|1] ""  PC
 SG_ S2P_Bal_CCanTimeOut_05 : 55|1@1+ (1,0) [0|1] ""  PC
 SG_ S2P_Bal_CellOffLine_05 : 56|1@1+ (1,0) [0|1] ""  PC
 SG_ S2P_Bal_BalanceCircuitFault_05 : 57|1@1+ (1,0) [0|1] ""  PC
 SG_ S2P_Bal_CSCSourceVoltFault_05 : 58|1@1+ (1,0) [0|1] ""  PC
 SG_ S2P_Bal_CellVoltOverFault_05 : 59|1@1+ (1,0) [0|1] ""  PC
 SG_ S2P_Bal_CellVoltLowFault_05 : 60|1@1+ (1,0) [0|1] ""  PC
 SG_ S2P_Bal_CSCPCBTempFault_05 : 61|1@1+ (1,0) [0|1] ""  PC
 SG_ S2P_Bal_CSCSourceCurrLowFault_05 : 62|1@1+ (1,0) [0|1] ""  PC
 SG_ S2P_Bal_CSCSourceCurrOvrFault_05 : 63|1@1+ (1,0) [0|1] ""  PC

BO_ 2417487430 S2P_BL_Meg__06: 8 SBMU
 SG_ S2P_Bal_CSCNum_06 : 0|6@1+ (1,0) [0|63] ""  PC
 SG_ S2P_Bal_CellNum_06 : 6|6@1+ (1,0) [0|63] ""  PC
 SG_ S2P_Bal_Type_06 : 12|2@1+ (1,0) [0|3] ""  PC
 SG_ S2P_Bal_TimeRemain_06 : 14|9@1+ (1,0) [0|511] ""  PC
 SG_ S2P_Bal_DeltaVolt_06 : 23|10@1+ (1,0) [0|1023] ""  PC
 SG_ S2P_Bal_CSCPowerCurr_06 : 33|11@1+ (1,0) [0|2047] ""  PC
 SG_ S2P_Bal_TypeLevel_06 : 44|3@1+ (1,0) [0|7] ""  PC
 SG_ S2P_Bal_SystemStatus_06 : 47|2@1+ (1,0) [0|3] ""  PC
 SG_ S2P_Bal_Strategy_06 : 49|1@1+ (1,0) [0|1] ""  PC
 SG_ S2P_Bal_ForceBalMode_06 : 50|2@1+ (1,0) [0|3] ""  PC
 SG_ S2P_Bal_CellTempFault_06 : 52|1@1+ (1,0) [0|1] ""  PC
 SG_ S2P_Bal_CellVoltFail_06 : 53|1@1+ (1,0) [0|1] ""  PC
 SG_ S2P_Bal_CloseBalInstruct_06 : 54|1@1+ (1,0) [0|1] ""  PC
 SG_ S2P_Bal_CCanTimeOut_06 : 55|1@1+ (1,0) [0|1] ""  PC
 SG_ S2P_Bal_CellOffLine_06 : 56|1@1+ (1,0) [0|1] ""  PC
 SG_ S2P_Bal_BalanceCircuitFault_06 : 57|1@1+ (1,0) [0|1] ""  PC
 SG_ S2P_Bal_CSCSourceVoltFault_06 : 58|1@1+ (1,0) [0|1] ""  PC
 SG_ S2P_Bal_CellVoltOverFault_06 : 59|1@1+ (1,0) [0|1] ""  PC
 SG_ S2P_Bal_CellVoltLowFault_06 : 60|1@1+ (1,0) [0|1] ""  PC
 SG_ S2P_Bal_CSCPCBTempFault_06 : 61|1@1+ (1,0) [0|1] ""  PC
 SG_ S2P_Bal_CSCSourceCurrLowFault_06 : 62|1@1+ (1,0) [0|1] ""  PC
 SG_ S2P_Bal_CSCSourceCurrOvrFault_06 : 63|1@1+ (1,0) [0|1] ""  PC

BO_ 2417487431 S2P_BL_Meg__07: 8 SBMU
 SG_ S2P_Bal_CSCNum_07 : 0|6@1+ (1,0) [0|63] ""  PC
 SG_ S2P_Bal_CellNum_07 : 6|6@1+ (1,0) [0|63] ""  PC
 SG_ S2P_Bal_Type_07 : 12|2@1+ (1,0) [0|3] ""  PC
 SG_ S2P_Bal_TimeRemain_07 : 14|9@1+ (1,0) [0|511] ""  PC
 SG_ S2P_Bal_DeltaVolt_07 : 23|10@1+ (1,0) [0|1023] ""  PC
 SG_ S2P_Bal_CSCPowerCurr_07 : 33|11@1+ (1,0) [0|2047] ""  PC
 SG_ S2P_Bal_TypeLevel_07 : 44|3@1+ (1,0) [0|7] ""  PC
 SG_ S2P_Bal_SystemStatus_07 : 47|2@1+ (1,0) [0|3] ""  PC
 SG_ S2P_Bal_Strategy_07 : 49|1@1+ (1,0) [0|1] ""  PC
 SG_ S2P_Bal_ForceBalMode_07 : 50|2@1+ (1,0) [0|3] ""  PC
 SG_ S2P_Bal_CellTempFault_07 : 52|1@1+ (1,0) [0|1] ""  PC
 SG_ S2P_Bal_CellVoltFail_07 : 53|1@1+ (1,0) [0|1] ""  PC
 SG_ S2P_Bal_CloseBalInstruct_07 : 54|1@1+ (1,0) [0|1] ""  PC
 SG_ S2P_Bal_CCanTimeOut_07 : 55|1@1+ (1,0) [0|1] ""  PC
 SG_ S2P_Bal_CellOffLine_07 : 56|1@1+ (1,0) [0|1] ""  PC
 SG_ S2P_Bal_BalanceCircuitFault_07 : 57|1@1+ (1,0) [0|1] ""  PC
 SG_ S2P_Bal_CSCSourceVoltFault_07 : 58|1@1+ (1,0) [0|1] ""  PC
 SG_ S2P_Bal_CellVoltOverFault_07 : 59|1@1+ (1,0) [0|1] ""  PC
 SG_ S2P_Bal_CellVoltLowFault_07 : 60|1@1+ (1,0) [0|1] ""  PC
 SG_ S2P_Bal_CSCPCBTempFault_07 : 61|1@1+ (1,0) [0|1] ""  PC
 SG_ S2P_Bal_CSCSourceCurrLowFault_07 : 62|1@1+ (1,0) [0|1] ""  PC
 SG_ S2P_Bal_CSCSourceCurrOvrFault_07 : 63|1@1+ (1,0) [0|1] ""  PC

BO_ 2417487432 S2P_BL_Meg__08: 8 SBMU
 SG_ S2P_Bal_CSCNum_08 : 0|6@1+ (1,0) [0|63] ""  PC
 SG_ S2P_Bal_CellNum_08 : 6|6@1+ (1,0) [0|63] ""  PC
 SG_ S2P_Bal_Type_08 : 12|2@1+ (1,0) [0|3] ""  PC
 SG_ S2P_Bal_TimeRemain_08 : 14|9@1+ (1,0) [0|511] ""  PC
 SG_ S2P_Bal_DeltaVolt_08 : 23|10@1+ (1,0) [0|1023] ""  PC
 SG_ S2P_Bal_CSCPowerCurr_08 : 33|11@1+ (1,0) [0|2047] ""  PC
 SG_ S2P_Bal_TypeLevel_08 : 44|3@1+ (1,0) [0|7] ""  PC
 SG_ S2P_Bal_SystemStatus_08 : 47|2@1+ (1,0) [0|3] ""  PC
 SG_ S2P_Bal_Strategy_08 : 49|1@1+ (1,0) [0|1] ""  PC
 SG_ S2P_Bal_ForceBalMode_08 : 50|2@1+ (1,0) [0|3] ""  PC
 SG_ S2P_Bal_CellTempFault_08 : 52|1@1+ (1,0) [0|1] ""  PC
 SG_ S2P_Bal_CellVoltFail_08 : 53|1@1+ (1,0) [0|1] ""  PC
 SG_ S2P_Bal_CloseBalInstruct_08 : 54|1@1+ (1,0) [0|1] ""  PC
 SG_ S2P_Bal_CCanTimeOut_08 : 55|1@1+ (1,0) [0|1] ""  PC
 SG_ S2P_Bal_CellOffLine_08 : 56|1@1+ (1,0) [0|1] ""  PC
 SG_ S2P_Bal_BalanceCircuitFault_08 : 57|1@1+ (1,0) [0|1] ""  PC
 SG_ S2P_Bal_CSCSourceVoltFault_08 : 58|1@1+ (1,0) [0|1] ""  PC
 SG_ S2P_Bal_CellVoltOverFault_08 : 59|1@1+ (1,0) [0|1] ""  PC
 SG_ S2P_Bal_CellVoltLowFault_08 : 60|1@1+ (1,0) [0|1] ""  PC
 SG_ S2P_Bal_CSCPCBTempFault_08 : 61|1@1+ (1,0) [0|1] ""  PC
 SG_ S2P_Bal_CSCSourceCurrLowFault_08 : 62|1@1+ (1,0) [0|1] ""  PC
 SG_ S2P_Bal_CSCSourceCurrOvrFault_08 : 63|1@1+ (1,0) [0|1] ""  PC

BO_ 2417487433 S2P_BL_Meg__09: 8 SBMU
 SG_ S2P_Bal_CSCNum_09 : 0|6@1+ (1,0) [0|63] ""  PC
 SG_ S2P_Bal_CellNum_09 : 6|6@1+ (1,0) [0|63] ""  PC
 SG_ S2P_Bal_Type_09 : 12|2@1+ (1,0) [0|3] ""  PC
 SG_ S2P_Bal_TimeRemain_09 : 14|9@1+ (1,0) [0|511] ""  PC
 SG_ S2P_Bal_DeltaVolt_09 : 23|10@1+ (1,0) [0|1023] ""  PC
 SG_ S2P_Bal_CSCPowerCurr_09 : 33|11@1+ (1,0) [0|2047] ""  PC
 SG_ S2P_Bal_TypeLevel_09 : 44|3@1+ (1,0) [0|7] ""  PC
 SG_ S2P_Bal_SystemStatus_09 : 47|2@1+ (1,0) [0|3] ""  PC
 SG_ S2P_Bal_Strategy_09 : 49|1@1+ (1,0) [0|1] ""  PC
 SG_ S2P_Bal_ForceBalMode_09 : 50|2@1+ (1,0) [0|3] ""  PC
 SG_ S2P_Bal_CellTempFault_09 : 52|1@1+ (1,0) [0|1] ""  PC
 SG_ S2P_Bal_CellVoltFail_09 : 53|1@1+ (1,0) [0|1] ""  PC
 SG_ S2P_Bal_CloseBalInstruct_09 : 54|1@1+ (1,0) [0|1] ""  PC
 SG_ S2P_Bal_CCanTimeOut_09 : 55|1@1+ (1,0) [0|1] ""  PC
 SG_ S2P_Bal_CellOffLine_09 : 56|1@1+ (1,0) [0|1] ""  PC
 SG_ S2P_Bal_BalanceCircuitFault_09 : 57|1@1+ (1,0) [0|1] ""  PC
 SG_ S2P_Bal_CSCSourceVoltFault_09 : 58|1@1+ (1,0) [0|1] ""  PC
 SG_ S2P_Bal_CellVoltOverFault_09 : 59|1@1+ (1,0) [0|1] ""  PC
 SG_ S2P_Bal_CellVoltLowFault_09 : 60|1@1+ (1,0) [0|1] ""  PC
 SG_ S2P_Bal_CSCPCBTempFault_09 : 61|1@1+ (1,0) [0|1] ""  PC
 SG_ S2P_Bal_CSCSourceCurrLowFault_09 : 62|1@1+ (1,0) [0|1] ""  PC
 SG_ S2P_Bal_CSCSourceCurrOvrFault_09 : 63|1@1+ (1,0) [0|1] ""  PC

BO_ 2417487434 S2P_BL_Meg__10: 8 SBMU
 SG_ S2P_Bal_CSCNum_10 : 0|6@1+ (1,0) [0|63] ""  PC
 SG_ S2P_Bal_CellNum_10 : 6|6@1+ (1,0) [0|63] ""  PC
 SG_ S2P_Bal_Type_10 : 12|2@1+ (1,0) [0|3] ""  PC
 SG_ S2P_Bal_TimeRemain_10 : 14|9@1+ (1,0) [0|511] ""  PC
 SG_ S2P_Bal_DeltaVolt_10 : 23|10@1+ (1,0) [0|1023] ""  PC
 SG_ S2P_Bal_CSCPowerCurr_10 : 33|11@1+ (1,0) [0|2047] ""  PC
 SG_ S2P_Bal_TypeLevel_10 : 44|3@1+ (1,0) [0|7] ""  PC
 SG_ S2P_Bal_SystemStatus_10 : 47|2@1+ (1,0) [0|3] ""  PC
 SG_ S2P_Bal_Strategy_10 : 49|1@1+ (1,0) [0|1] ""  PC
 SG_ S2P_Bal_ForceBalMode_10 : 50|2@1+ (1,0) [0|3] ""  PC
 SG_ S2P_Bal_CellTempFault_10 : 52|1@1+ (1,0) [0|1] ""  PC
 SG_ S2P_Bal_CellVoltFail_10 : 53|1@1+ (1,0) [0|1] ""  PC
 SG_ S2P_Bal_CloseBalInstruct_10 : 54|1@1+ (1,0) [0|1] ""  PC
 SG_ S2P_Bal_CCanTimeOut_10 : 55|1@1+ (1,0) [0|1] ""  PC
 SG_ S2P_Bal_CellOffLine_10 : 56|1@1+ (1,0) [0|1] ""  PC
 SG_ S2P_Bal_BalanceCircuitFault_10 : 57|1@1+ (1,0) [0|1] ""  PC
 SG_ S2P_Bal_CSCSourceVoltFault_10 : 58|1@1+ (1,0) [0|1] ""  PC
 SG_ S2P_Bal_CellVoltOverFault_10 : 59|1@1+ (1,0) [0|1] ""  PC
 SG_ S2P_Bal_CellVoltLowFault_10 : 60|1@1+ (1,0) [0|1] ""  PC
 SG_ S2P_Bal_CSCPCBTempFault_10 : 61|1@1+ (1,0) [0|1] ""  PC
 SG_ S2P_Bal_CSCSourceCurrLowFault_10 : 62|1@1+ (1,0) [0|1] ""  PC
 SG_ S2P_Bal_CSCSourceCurrOvrFault_10 : 63|1@1+ (1,0) [0|1] ""  PC

BO_ 2417487435 S2P_BL_Meg__11: 8 SBMU
 SG_ S2P_Bal_CSCNum_11 : 0|6@1+ (1,0) [0|63] ""  PC
 SG_ S2P_Bal_CellNum_11 : 6|6@1+ (1,0) [0|63] ""  PC
 SG_ S2P_Bal_Type_11 : 12|2@1+ (1,0) [0|3] ""  PC
 SG_ S2P_Bal_TimeRemain_11 : 14|9@1+ (1,0) [0|511] ""  PC
 SG_ S2P_Bal_DeltaVolt_11 : 23|10@1+ (1,0) [0|1023] ""  PC
 SG_ S2P_Bal_CSCPowerCurr_11 : 33|11@1+ (1,0) [0|2047] ""  PC
 SG_ S2P_Bal_TypeLevel_11 : 44|3@1+ (1,0) [0|7] ""  PC
 SG_ S2P_Bal_SystemStatus_11 : 47|2@1+ (1,0) [0|3] ""  PC
 SG_ S2P_Bal_Strategy_11 : 49|1@1+ (1,0) [0|1] ""  PC
 SG_ S2P_Bal_ForceBalMode_11 : 50|2@1+ (1,0) [0|3] ""  PC
 SG_ S2P_Bal_CellTempFault_11 : 52|1@1+ (1,0) [0|1] ""  PC
 SG_ S2P_Bal_CellVoltFail_11 : 53|1@1+ (1,0) [0|1] ""  PC
 SG_ S2P_Bal_CloseBalInstruct_11 : 54|1@1+ (1,0) [0|1] ""  PC
 SG_ S2P_Bal_CCanTimeOut_11 : 55|1@1+ (1,0) [0|1] ""  PC
 SG_ S2P_Bal_CellOffLine_11 : 56|1@1+ (1,0) [0|1] ""  PC
 SG_ S2P_Bal_BalanceCircuitFault_11 : 57|1@1+ (1,0) [0|1] ""  PC
 SG_ S2P_Bal_CSCSourceVoltFault_11 : 58|1@1+ (1,0) [0|1] ""  PC
 SG_ S2P_Bal_CellVoltOverFault_11 : 59|1@1+ (1,0) [0|1] ""  PC
 SG_ S2P_Bal_CellVoltLowFault_11 : 60|1@1+ (1,0) [0|1] ""  PC
 SG_ S2P_Bal_CSCPCBTempFault_11 : 61|1@1+ (1,0) [0|1] ""  PC
 SG_ S2P_Bal_CSCSourceCurrLowFault_11 : 62|1@1+ (1,0) [0|1] ""  PC
 SG_ S2P_Bal_CSCSourceCurrOvrFault_11 : 63|1@1+ (1,0) [0|1] ""  PC

BO_ 2417487436 S2P_BL_Meg__12: 8 SBMU
 SG_ S2P_Bal_CSCNum_12 : 0|6@1+ (1,0) [0|63] ""  PC
 SG_ S2P_Bal_CellNum_12 : 6|6@1+ (1,0) [0|63] ""  PC
 SG_ S2P_Bal_Type_12 : 12|2@1+ (1,0) [0|3] ""  PC
 SG_ S2P_Bal_TimeRemain_12 : 14|9@1+ (1,0) [0|511] ""  PC
 SG_ S2P_Bal_DeltaVolt_12 : 23|10@1+ (1,0) [0|1023] ""  PC
 SG_ S2P_Bal_CSCPowerCurr_12 : 33|11@1+ (1,0) [0|2047] ""  PC
 SG_ S2P_Bal_TypeLevel_12 : 44|3@1+ (1,0) [0|7] ""  PC
 SG_ S2P_Bal_SystemStatus_12 : 47|2@1+ (1,0) [0|3] ""  PC
 SG_ S2P_Bal_Strategy_12 : 49|1@1+ (1,0) [0|1] ""  PC
 SG_ S2P_Bal_ForceBalMode_12 : 50|2@1+ (1,0) [0|3] ""  PC
 SG_ S2P_Bal_CellTempFault_12 : 52|1@1+ (1,0) [0|1] ""  PC
 SG_ S2P_Bal_CellVoltFail_12 : 53|1@1+ (1,0) [0|1] ""  PC
 SG_ S2P_Bal_CloseBalInstruct_12 : 54|1@1+ (1,0) [0|1] ""  PC
 SG_ S2P_Bal_CCanTimeOut_12 : 55|1@1+ (1,0) [0|1] ""  PC
 SG_ S2P_Bal_CellOffLine_12 : 56|1@1+ (1,0) [0|1] ""  PC
 SG_ S2P_Bal_BalanceCircuitFault_12 : 57|1@1+ (1,0) [0|1] ""  PC
 SG_ S2P_Bal_CSCSourceVoltFault_12 : 58|1@1+ (1,0) [0|1] ""  PC
 SG_ S2P_Bal_CellVoltOverFault_12 : 59|1@1+ (1,0) [0|1] ""  PC
 SG_ S2P_Bal_CellVoltLowFault_12 : 60|1@1+ (1,0) [0|1] ""  PC
 SG_ S2P_Bal_CSCPCBTempFault_12 : 61|1@1+ (1,0) [0|1] ""  PC
 SG_ S2P_Bal_CSCSourceCurrLowFault_12 : 62|1@1+ (1,0) [0|1] ""  PC
 SG_ S2P_Bal_CSCSourceCurrOvrFault_12 : 63|1@1+ (1,0) [0|1] ""  PC

BO_ 2417487437 S2P_BL_Meg__13: 8 SBMU
 SG_ S2P_Bal_CSCNum_13 : 0|6@1+ (1,0) [0|63] ""  PC
 SG_ S2P_Bal_CellNum_13 : 6|6@1+ (1,0) [0|63] ""  PC
 SG_ S2P_Bal_Type_13 : 12|2@1+ (1,0) [0|3] ""  PC
 SG_ S2P_Bal_TimeRemain_13 : 14|9@1+ (1,0) [0|511] ""  PC
 SG_ S2P_Bal_DeltaVolt_13 : 23|10@1+ (1,0) [0|1023] ""  PC
 SG_ S2P_Bal_CSCPowerCurr_13 : 33|11@1+ (1,0) [0|2047] ""  PC
 SG_ S2P_Bal_TypeLevel_13 : 44|3@1+ (1,0) [0|7] ""  PC
 SG_ S2P_Bal_SystemStatus_13 : 47|2@1+ (1,0) [0|3] ""  PC
 SG_ S2P_Bal_Strategy_13 : 49|1@1+ (1,0) [0|1] ""  PC
 SG_ S2P_Bal_ForceBalMode_13 : 50|2@1+ (1,0) [0|3] ""  PC
 SG_ S2P_Bal_CellTempFault_13 : 52|1@1+ (1,0) [0|1] ""  PC
 SG_ S2P_Bal_CellVoltFail_13 : 53|1@1+ (1,0) [0|1] ""  PC
 SG_ S2P_Bal_CloseBalInstruct_13 : 54|1@1+ (1,0) [0|1] ""  PC
 SG_ S2P_Bal_CCanTimeOut_13 : 55|1@1+ (1,0) [0|1] ""  PC
 SG_ S2P_Bal_CellOffLine_13 : 56|1@1+ (1,0) [0|1] ""  PC
 SG_ S2P_Bal_BalanceCircuitFault_13 : 57|1@1+ (1,0) [0|1] ""  PC
 SG_ S2P_Bal_CSCSourceVoltFault_13 : 58|1@1+ (1,0) [0|1] ""  PC
 SG_ S2P_Bal_CellVoltOverFault_13 : 59|1@1+ (1,0) [0|1] ""  PC
 SG_ S2P_Bal_CellVoltLowFault_13 : 60|1@1+ (1,0) [0|1] ""  PC
 SG_ S2P_Bal_CSCPCBTempFault_13 : 61|1@1+ (1,0) [0|1] ""  PC
 SG_ S2P_Bal_CSCSourceCurrLowFault_13 : 62|1@1+ (1,0) [0|1] ""  PC
 SG_ S2P_Bal_CSCSourceCurrOvrFault_13 : 63|1@1+ (1,0) [0|1] ""  PC

BO_ 2417487438 S2P_BL_Meg__14: 8 SBMU
 SG_ S2P_Bal_CSCNum_14 : 0|6@1+ (1,0) [0|63] ""  PC
 SG_ S2P_Bal_CellNum_14 : 6|6@1+ (1,0) [0|63] ""  PC
 SG_ S2P_Bal_Type_14 : 12|2@1+ (1,0) [0|3] ""  PC
 SG_ S2P_Bal_TimeRemain_14 : 14|9@1+ (1,0) [0|511] ""  PC
 SG_ S2P_Bal_DeltaVolt_14 : 23|10@1+ (1,0) [0|1023] ""  PC
 SG_ S2P_Bal_CSCPowerCurr_14 : 33|11@1+ (1,0) [0|2047] ""  PC
 SG_ S2P_Bal_TypeLevel_14 : 44|3@1+ (1,0) [0|7] ""  PC
 SG_ S2P_Bal_SystemStatus_14 : 47|2@1+ (1,0) [0|3] ""  PC
 SG_ S2P_Bal_Strategy_14 : 49|1@1+ (1,0) [0|1] ""  PC
 SG_ S2P_Bal_ForceBalMode_14 : 50|2@1+ (1,0) [0|3] ""  PC
 SG_ S2P_Bal_CellTempFault_14 : 52|1@1+ (1,0) [0|1] ""  PC
 SG_ S2P_Bal_CellVoltFail_14 : 53|1@1+ (1,0) [0|1] ""  PC
 SG_ S2P_Bal_CloseBalInstruct_14 : 54|1@1+ (1,0) [0|1] ""  PC
 SG_ S2P_Bal_CCanTimeOut_14 : 55|1@1+ (1,0) [0|1] ""  PC
 SG_ S2P_Bal_CellOffLine_14 : 56|1@1+ (1,0) [0|1] ""  PC
 SG_ S2P_Bal_BalanceCircuitFault_14 : 57|1@1+ (1,0) [0|1] ""  PC
 SG_ S2P_Bal_CSCSourceVoltFault_14 : 58|1@1+ (1,0) [0|1] ""  PC
 SG_ S2P_Bal_CellVoltOverFault_14 : 59|1@1+ (1,0) [0|1] ""  PC
 SG_ S2P_Bal_CellVoltLowFault_14 : 60|1@1+ (1,0) [0|1] ""  PC
 SG_ S2P_Bal_CSCPCBTempFault_14 : 61|1@1+ (1,0) [0|1] ""  PC
 SG_ S2P_Bal_CSCSourceCurrLowFault_14 : 62|1@1+ (1,0) [0|1] ""  PC
 SG_ S2P_Bal_CSCSourceCurrOvrFault_14 : 63|1@1+ (1,0) [0|1] ""  PC

BO_ 2417487439 S2P_BL_Meg__15: 8 SBMU
 SG_ S2P_Bal_CSCNum_15 : 0|6@1+ (1,0) [0|63] ""  PC
 SG_ S2P_Bal_CellNum_15 : 6|6@1+ (1,0) [0|63] ""  PC
 SG_ S2P_Bal_Type_15 : 12|2@1+ (1,0) [0|3] ""  PC
 SG_ S2P_Bal_TimeRemain_15 : 14|9@1+ (1,0) [0|511] ""  PC
 SG_ S2P_Bal_DeltaVolt_15 : 23|10@1+ (1,0) [0|1023] ""  PC
 SG_ S2P_Bal_CSCPowerCurr_15 : 33|11@1+ (1,0) [0|2047] ""  PC
 SG_ S2P_Bal_TypeLevel_15 : 44|3@1+ (1,0) [0|7] ""  PC
 SG_ S2P_Bal_SystemStatus_15 : 47|2@1+ (1,0) [0|3] ""  PC
 SG_ S2P_Bal_Strategy_15 : 49|1@1+ (1,0) [0|1] ""  PC
 SG_ S2P_Bal_ForceBalMode_15 : 50|2@1+ (1,0) [0|3] ""  PC
 SG_ S2P_Bal_CellTempFault_15 : 52|1@1+ (1,0) [0|1] ""  PC
 SG_ S2P_Bal_CellVoltFail_15 : 53|1@1+ (1,0) [0|1] ""  PC
 SG_ S2P_Bal_CloseBalInstruct_15 : 54|1@1+ (1,0) [0|1] ""  PC
 SG_ S2P_Bal_CCanTimeOut_15 : 55|1@1+ (1,0) [0|1] ""  PC
 SG_ S2P_Bal_CellOffLine_15 : 56|1@1+ (1,0) [0|1] ""  PC
 SG_ S2P_Bal_BalanceCircuitFault_15 : 57|1@1+ (1,0) [0|1] ""  PC
 SG_ S2P_Bal_CSCSourceVoltFault_15 : 58|1@1+ (1,0) [0|1] ""  PC
 SG_ S2P_Bal_CellVoltOverFault_15 : 59|1@1+ (1,0) [0|1] ""  PC
 SG_ S2P_Bal_CellVoltLowFault_15 : 60|1@1+ (1,0) [0|1] ""  PC
 SG_ S2P_Bal_CSCPCBTempFault_15 : 61|1@1+ (1,0) [0|1] ""  PC
 SG_ S2P_Bal_CSCSourceCurrLowFault_15 : 62|1@1+ (1,0) [0|1] ""  PC
 SG_ S2P_Bal_CSCSourceCurrOvrFault_15 : 63|1@1+ (1,0) [0|1] ""  PC

BO_ 2417487440 S2P_BL_Meg__16: 8 SBMU
 SG_ S2P_Bal_CSCNum_16 : 0|6@1+ (1,0) [0|63] ""  PC
 SG_ S2P_Bal_CellNum_16 : 6|6@1+ (1,0) [0|63] ""  PC
 SG_ S2P_Bal_Type_16 : 12|2@1+ (1,0) [0|3] ""  PC
 SG_ S2P_Bal_TimeRemain_16 : 14|9@1+ (1,0) [0|511] ""  PC
 SG_ S2P_Bal_DeltaVolt_16 : 23|10@1+ (1,0) [0|1023] ""  PC
 SG_ S2P_Bal_CSCPowerCurr_16 : 33|11@1+ (1,0) [0|2047] ""  PC
 SG_ S2P_Bal_TypeLevel_16 : 44|3@1+ (1,0) [0|7] ""  PC
 SG_ S2P_Bal_SystemStatus_16 : 47|2@1+ (1,0) [0|3] ""  PC
 SG_ S2P_Bal_Strategy_16 : 49|1@1+ (1,0) [0|1] ""  PC
 SG_ S2P_Bal_ForceBalMode_16 : 50|2@1+ (1,0) [0|3] ""  PC
 SG_ S2P_Bal_CellTempFault_16 : 52|1@1+ (1,0) [0|1] ""  PC
 SG_ S2P_Bal_CellVoltFail_16 : 53|1@1+ (1,0) [0|1] ""  PC
 SG_ S2P_Bal_CloseBalInstruct_16 : 54|1@1+ (1,0) [0|1] ""  PC
 SG_ S2P_Bal_CCanTimeOut_16 : 55|1@1+ (1,0) [0|1] ""  PC
 SG_ S2P_Bal_CellOffLine_16 : 56|1@1+ (1,0) [0|1] ""  PC
 SG_ S2P_Bal_BalanceCircuitFault_16 : 57|1@1+ (1,0) [0|1] ""  PC
 SG_ S2P_Bal_CSCSourceVoltFault_16 : 58|1@1+ (1,0) [0|1] ""  PC
 SG_ S2P_Bal_CellVoltOverFault_16 : 59|1@1+ (1,0) [0|1] ""  PC
 SG_ S2P_Bal_CellVoltLowFault_16 : 60|1@1+ (1,0) [0|1] ""  PC
 SG_ S2P_Bal_CSCPCBTempFault_16 : 61|1@1+ (1,0) [0|1] ""  PC
 SG_ S2P_Bal_CSCSourceCurrLowFault_16 : 62|1@1+ (1,0) [0|1] ""  PC
 SG_ S2P_Bal_CSCSourceCurrOvrFault_16 : 63|1@1+ (1,0) [0|1] ""  PC

BO_ 2417487441 S2P_BL_Meg__17: 8 SBMU
 SG_ S2P_Bal_CSCNum_17 : 0|6@1+ (1,0) [0|63] ""  PC
 SG_ S2P_Bal_CellNum_17 : 6|6@1+ (1,0) [0|63] ""  PC
 SG_ S2P_Bal_Type_17 : 12|2@1+ (1,0) [0|3] ""  PC
 SG_ S2P_Bal_TimeRemain_17 : 14|9@1+ (1,0) [0|511] ""  PC
 SG_ S2P_Bal_DeltaVolt_17 : 23|10@1+ (1,0) [0|1023] ""  PC
 SG_ S2P_Bal_CSCPowerCurr_17 : 33|11@1+ (1,0) [0|2047] ""  PC
 SG_ S2P_Bal_TypeLevel_17 : 44|3@1+ (1,0) [0|7] ""  PC
 SG_ S2P_Bal_SystemStatus_17 : 47|2@1+ (1,0) [0|3] ""  PC
 SG_ S2P_Bal_Strategy_17 : 49|1@1+ (1,0) [0|1] ""  PC
 SG_ S2P_Bal_ForceBalMode_17 : 50|2@1+ (1,0) [0|3] ""  PC
 SG_ S2P_Bal_CellTempFault_17 : 52|1@1+ (1,0) [0|1] ""  PC
 SG_ S2P_Bal_CellVoltFail_17 : 53|1@1+ (1,0) [0|1] ""  PC
 SG_ S2P_Bal_CloseBalInstruct_17 : 54|1@1+ (1,0) [0|1] ""  PC
 SG_ S2P_Bal_CCanTimeOut_17 : 55|1@1+ (1,0) [0|1] ""  PC
 SG_ S2P_Bal_CellOffLine_17 : 56|1@1+ (1,0) [0|1] ""  PC
 SG_ S2P_Bal_BalanceCircuitFault_17 : 57|1@1+ (1,0) [0|1] ""  PC
 SG_ S2P_Bal_CSCSourceVoltFault_17 : 58|1@1+ (1,0) [0|1] ""  PC
 SG_ S2P_Bal_CellVoltOverFault_17 : 59|1@1+ (1,0) [0|1] ""  PC
 SG_ S2P_Bal_CellVoltLowFault_17 : 60|1@1+ (1,0) [0|1] ""  PC
 SG_ S2P_Bal_CSCPCBTempFault_17 : 61|1@1+ (1,0) [0|1] ""  PC
 SG_ S2P_Bal_CSCSourceCurrLowFault_17 : 62|1@1+ (1,0) [0|1] ""  PC
 SG_ S2P_Bal_CSCSourceCurrOvrFault_17 : 63|1@1+ (1,0) [0|1] ""  PC

BO_ 2417487442 S2P_BL_Meg__18: 8 SBMU
 SG_ S2P_Bal_CSCNum_18 : 0|6@1+ (1,0) [0|63] ""  PC
 SG_ S2P_Bal_CellNum_18 : 6|6@1+ (1,0) [0|63] ""  PC
 SG_ S2P_Bal_Type_18 : 12|2@1+ (1,0) [0|3] ""  PC
 SG_ S2P_Bal_TimeRemain_18 : 14|9@1+ (1,0) [0|511] ""  PC
 SG_ S2P_Bal_DeltaVolt_18 : 23|10@1+ (1,0) [0|1023] ""  PC
 SG_ S2P_Bal_CSCPowerCurr_18 : 33|11@1+ (1,0) [0|2047] ""  PC
 SG_ S2P_Bal_TypeLevel_18 : 44|3@1+ (1,0) [0|7] ""  PC
 SG_ S2P_Bal_SystemStatus_18 : 47|2@1+ (1,0) [0|3] ""  PC
 SG_ S2P_Bal_Strategy_18 : 49|1@1+ (1,0) [0|1] ""  PC
 SG_ S2P_Bal_ForceBalMode_18 : 50|2@1+ (1,0) [0|3] ""  PC
 SG_ S2P_Bal_CellTempFault_18 : 52|1@1+ (1,0) [0|1] ""  PC
 SG_ S2P_Bal_CellVoltFail_18 : 53|1@1+ (1,0) [0|1] ""  PC
 SG_ S2P_Bal_CloseBalInstruct_18 : 54|1@1+ (1,0) [0|1] ""  PC
 SG_ S2P_Bal_CCanTimeOut_18 : 55|1@1+ (1,0) [0|1] ""  PC
 SG_ S2P_Bal_CellOffLine_18 : 56|1@1+ (1,0) [0|1] ""  PC
 SG_ S2P_Bal_BalanceCircuitFault_18 : 57|1@1+ (1,0) [0|1] ""  PC
 SG_ S2P_Bal_CSCSourceVoltFault_18 : 58|1@1+ (1,0) [0|1] ""  PC
 SG_ S2P_Bal_CellVoltOverFault_18 : 59|1@1+ (1,0) [0|1] ""  PC
 SG_ S2P_Bal_CellVoltLowFault_18 : 60|1@1+ (1,0) [0|1] ""  PC
 SG_ S2P_Bal_CSCPCBTempFault_18 : 61|1@1+ (1,0) [0|1] ""  PC
 SG_ S2P_Bal_CSCSourceCurrLowFault_18 : 62|1@1+ (1,0) [0|1] ""  PC
 SG_ S2P_Bal_CSCSourceCurrOvrFault_18 : 63|1@1+ (1,0) [0|1] ""  PC

BO_ 2417487443 S2P_BL_Meg__19: 8 SBMU
 SG_ S2P_Bal_CSCNum_19 : 0|6@1+ (1,0) [0|63] ""  PC
 SG_ S2P_Bal_CellNum_19 : 6|6@1+ (1,0) [0|63] ""  PC
 SG_ S2P_Bal_Type_19 : 12|2@1+ (1,0) [0|3] ""  PC
 SG_ S2P_Bal_TimeRemain_19 : 14|9@1+ (1,0) [0|511] ""  PC
 SG_ S2P_Bal_DeltaVolt_19 : 23|10@1+ (1,0) [0|1023] ""  PC
 SG_ S2P_Bal_CSCPowerCurr_19 : 33|11@1+ (1,0) [0|2047] ""  PC
 SG_ S2P_Bal_TypeLevel_19 : 44|3@1+ (1,0) [0|7] ""  PC
 SG_ S2P_Bal_SystemStatus_19 : 47|2@1+ (1,0) [0|3] ""  PC
 SG_ S2P_Bal_Strategy_19 : 49|1@1+ (1,0) [0|1] ""  PC
 SG_ S2P_Bal_ForceBalMode_19 : 50|2@1+ (1,0) [0|3] ""  PC
 SG_ S2P_Bal_CellTempFault_19 : 52|1@1+ (1,0) [0|1] ""  PC
 SG_ S2P_Bal_CellVoltFail_19 : 53|1@1+ (1,0) [0|1] ""  PC
 SG_ S2P_Bal_CloseBalInstruct_19 : 54|1@1+ (1,0) [0|1] ""  PC
 SG_ S2P_Bal_CCanTimeOut_19 : 55|1@1+ (1,0) [0|1] ""  PC
 SG_ S2P_Bal_CellOffLine_19 : 56|1@1+ (1,0) [0|1] ""  PC
 SG_ S2P_Bal_BalanceCircuitFault_19 : 57|1@1+ (1,0) [0|1] ""  PC
 SG_ S2P_Bal_CSCSourceVoltFault_19 : 58|1@1+ (1,0) [0|1] ""  PC
 SG_ S2P_Bal_CellVoltOverFault_19 : 59|1@1+ (1,0) [0|1] ""  PC
 SG_ S2P_Bal_CellVoltLowFault_19 : 60|1@1+ (1,0) [0|1] ""  PC
 SG_ S2P_Bal_CSCPCBTempFault_19 : 61|1@1+ (1,0) [0|1] ""  PC
 SG_ S2P_Bal_CSCSourceCurrLowFault_19 : 62|1@1+ (1,0) [0|1] ""  PC
 SG_ S2P_Bal_CSCSourceCurrOvrFault_19 : 63|1@1+ (1,0) [0|1] ""  PC

BO_ 2417487444 S2P_BL_Meg__20: 8 SBMU
 SG_ S2P_Bal_CSCNum_20 : 0|6@1+ (1,0) [0|63] ""  PC
 SG_ S2P_Bal_CellNum_20 : 6|6@1+ (1,0) [0|63] ""  PC
 SG_ S2P_Bal_Type_20 : 12|2@1+ (1,0) [0|3] ""  PC
 SG_ S2P_Bal_TimeRemain_20 : 14|9@1+ (1,0) [0|511] ""  PC
 SG_ S2P_Bal_DeltaVolt_20 : 23|10@1+ (1,0) [0|1023] ""  PC
 SG_ S2P_Bal_CSCPowerCurr_20 : 33|11@1+ (1,0) [0|2047] ""  PC
 SG_ S2P_Bal_TypeLevel_20 : 44|3@1+ (1,0) [0|7] ""  PC
 SG_ S2P_Bal_SystemStatus_20 : 47|2@1+ (1,0) [0|3] ""  PC
 SG_ S2P_Bal_Strategy_20 : 49|1@1+ (1,0) [0|1] ""  PC
 SG_ S2P_Bal_ForceBalMode_20 : 50|2@1+ (1,0) [0|3] ""  PC
 SG_ S2P_Bal_CellTempFault_20 : 52|1@1+ (1,0) [0|1] ""  PC
 SG_ S2P_Bal_CellVoltFail_20 : 53|1@1+ (1,0) [0|1] ""  PC
 SG_ S2P_Bal_CloseBalInstruct_20 : 54|1@1+ (1,0) [0|1] ""  PC
 SG_ S2P_Bal_CCanTimeOut_20 : 55|1@1+ (1,0) [0|1] ""  PC
 SG_ S2P_Bal_CellOffLine_20 : 56|1@1+ (1,0) [0|1] ""  PC
 SG_ S2P_Bal_BalanceCircuitFault_20 : 57|1@1+ (1,0) [0|1] ""  PC
 SG_ S2P_Bal_CSCSourceVoltFault_20 : 58|1@1+ (1,0) [0|1] ""  PC
 SG_ S2P_Bal_CellVoltOverFault_20 : 59|1@1+ (1,0) [0|1] ""  PC
 SG_ S2P_Bal_CellVoltLowFault_20 : 60|1@1+ (1,0) [0|1] ""  PC
 SG_ S2P_Bal_CSCPCBTempFault_20 : 61|1@1+ (1,0) [0|1] ""  PC
 SG_ S2P_Bal_CSCSourceCurrLowFault_20 : 62|1@1+ (1,0) [0|1] ""  PC
 SG_ S2P_Bal_CSCSourceCurrOvrFault_20 : 63|1@1+ (1,0) [0|1] ""  PC

BO_ 2417487445 S2P_BL_Meg__21: 8 SBMU
 SG_ S2P_Bal_CSCNum_21 : 0|6@1+ (1,0) [0|63] ""  PC
 SG_ S2P_Bal_CellNum_21 : 6|6@1+ (1,0) [0|63] ""  PC
 SG_ S2P_Bal_Type_21 : 12|2@1+ (1,0) [0|3] ""  PC
 SG_ S2P_Bal_TimeRemain_21 : 14|9@1+ (1,0) [0|511] ""  PC
 SG_ S2P_Bal_DeltaVolt_21 : 23|10@1+ (1,0) [0|1023] ""  PC
 SG_ S2P_Bal_CSCPowerCurr_21 : 33|11@1+ (1,0) [0|2047] ""  PC
 SG_ S2P_Bal_TypeLevel_21 : 44|3@1+ (1,0) [0|7] ""  PC
 SG_ S2P_Bal_SystemStatus_21 : 47|2@1+ (1,0) [0|3] ""  PC
 SG_ S2P_Bal_Strategy_21 : 49|1@1+ (1,0) [0|1] ""  PC
 SG_ S2P_Bal_ForceBalMode_21 : 50|2@1+ (1,0) [0|3] ""  PC
 SG_ S2P_Bal_CellTempFault_21 : 52|1@1+ (1,0) [0|1] ""  PC
 SG_ S2P_Bal_CellVoltFail_21 : 53|1@1+ (1,0) [0|1] ""  PC
 SG_ S2P_Bal_CloseBalInstruct_21 : 54|1@1+ (1,0) [0|1] ""  PC
 SG_ S2P_Bal_CCanTimeOut_21 : 55|1@1+ (1,0) [0|1] ""  PC
 SG_ S2P_Bal_CellOffLine_21 : 56|1@1+ (1,0) [0|1] ""  PC
 SG_ S2P_Bal_BalanceCircuitFault_21 : 57|1@1+ (1,0) [0|1] ""  PC
 SG_ S2P_Bal_CSCSourceVoltFault_21 : 58|1@1+ (1,0) [0|1] ""  PC
 SG_ S2P_Bal_CellVoltOverFault_21 : 59|1@1+ (1,0) [0|1] ""  PC
 SG_ S2P_Bal_CellVoltLowFault_21 : 60|1@1+ (1,0) [0|1] ""  PC
 SG_ S2P_Bal_CSCPCBTempFault_21 : 61|1@1+ (1,0) [0|1] ""  PC
 SG_ S2P_Bal_CSCSourceCurrLowFault_21 : 62|1@1+ (1,0) [0|1] ""  PC
 SG_ S2P_Bal_CSCSourceCurrOvrFault_21 : 63|1@1+ (1,0) [0|1] ""  PC

CM_ SG_ 2400579193 CSC_B_S_No_57 "CSC号";
CM_ SG_ 2400579193 State_Balance_Status_57 "均衡状态";
CM_ SG_ 2400579193 State_Balance_Fault_57 "均衡关闭故障";
CM_ SG_ 2400579194 CSC_B_S_No_58 "CSC号";
CM_ SG_ 2400579194 State_Balance_Status_58 "均衡状态";
CM_ SG_ 2400579194 State_Balance_Fault_58 "均衡关闭故障";
CM_ SG_ 2400579195 CSC_B_S_No_59 "CSC号";
CM_ SG_ 2400579195 State_Balance_Status_59 "均衡状态";
CM_ SG_ 2400579195 State_Balance_Fault_59 "均衡关闭故障";
CM_ SG_ 2400579196 CSC_B_S_No_60 "CSC号";
CM_ SG_ 2400579196 State_Balance_Status_60 "均衡状态";
CM_ SG_ 2400579196 State_Balance_Fault_60 "均衡关闭故障";
CM_ SG_ 2400579197 CSC_B_S_No_61 "CSC号";
CM_ SG_ 2400579197 State_Balance_Status_61 "均衡状态";
CM_ SG_ 2400579197 State_Balance_Fault_61 "均衡关闭故障";
CM_ SG_ 2400579198 CSC_B_S_No_62 "CSC号";
CM_ SG_ 2400579198 State_Balance_Status_62 "均衡状态";
CM_ SG_ 2400579198 State_Balance_Fault_62 "均衡关闭故障";
CM_ SG_ 2400579199 CSC_B_S_No_63 "CSC号";
CM_ SG_ 2400579199 State_Balance_Status_63 "均衡状态";
CM_ SG_ 2400579199 State_Balance_Fault_63 "均衡关闭故障";
CM_ SG_ 2400513601 S2P_TankVol_K_01 "校准后电柜采样电压的K值";
CM_ SG_ 2400513601 S2P_TankVol_B_01 "校准后电柜采样电压的B值（预留）";
CM_ SG_ 2400513601 S2P_TankVol_CalResult_01 "电柜采样电压校准结果反馈                              备注：高压采样k值校准结果";
CM_ SG_ 2400513602 S2P_TankVol_K_02 "校准后电柜采样电压的K值";
CM_ SG_ 2400513602 S2P_TankVol_B_02 "校准后电柜采样电压的B值（预留）";
CM_ SG_ 2400513602 S2P_TankVol_CalResult_02 "电柜采样电压校准结果反馈                              备注：高压采样k值校准结果";
CM_ SG_ 2400513603 S2P_TankVol_K_03 "校准后电柜采样电压的K值";
CM_ SG_ 2400513603 S2P_TankVol_B_03 "校准后电柜采样电压的B值（预留）";
CM_ SG_ 2400513603 S2P_TankVol_CalResult_03 "电柜采样电压校准结果反馈                              备注：高压采样k值校准结果";
CM_ SG_ 2400513604 S2P_TankVol_K_04 "校准后电柜采样电压的K值";
CM_ SG_ 2400513604 S2P_TankVol_B_04 "校准后电柜采样电压的B值（预留）";
CM_ SG_ 2400513604 S2P_TankVol_CalResult_04 "电柜采样电压校准结果反馈                              备注：高压采样k值校准结果";
CM_ SG_ 2400513605 S2P_TankVol_K_05 "校准后电柜采样电压的K值";
CM_ SG_ 2400513605 S2P_TankVol_B_05 "校准后电柜采样电压的B值（预留）";
CM_ SG_ 2400513605 S2P_TankVol_CalResult_05 "电柜采样电压校准结果反馈                              备注：高压采样k值校准结果";
CM_ SG_ 2400513606 S2P_TankVol_K_06 "校准后电柜采样电压的K值";
CM_ SG_ 2400513606 S2P_TankVol_B_06 "校准后电柜采样电压的B值（预留）";
CM_ SG_ 2400513606 S2P_TankVol_CalResult_06 "电柜采样电压校准结果反馈                              备注：高压采样k值校准结果";
CM_ SG_ 2400513607 S2P_TankVol_K_07 "校准后电柜采样电压的K值";
CM_ SG_ 2400513607 S2P_TankVol_B_07 "校准后电柜采样电压的B值（预留）";
CM_ SG_ 2400513607 S2P_TankVol_CalResult_07 "电柜采样电压校准结果反馈                              备注：高压采样k值校准结果";
CM_ SG_ 2400513608 S2P_TankVol_K_08 "校准后电柜采样电压的K值";
CM_ SG_ 2400513608 S2P_TankVol_B_08 "校准后电柜采样电压的B值（预留）";
CM_ SG_ 2400513608 S2P_TankVol_CalResult_08 "电柜采样电压校准结果反馈                              备注：高压采样k值校准结果";
CM_ SG_ 2400513609 S2P_TankVol_K_09 "校准后电柜采样电压的K值";
CM_ SG_ 2400513609 S2P_TankVol_B_09 "校准后电柜采样电压的B值（预留）";
CM_ SG_ 2400513609 S2P_TankVol_CalResult_09 "电柜采样电压校准结果反馈                              备注：高压采样k值校准结果";
CM_ SG_ 2400513610 S2P_TankVol_K_10 "校准后电柜采样电压的K值";
CM_ SG_ 2400513610 S2P_TankVol_B_10 "校准后电柜采样电压的B值（预留）";
CM_ SG_ 2400513610 S2P_TankVol_CalResult_10 "电柜采样电压校准结果反馈                              备注：高压采样k值校准结果";
CM_ SG_ 2400513611 S2P_TankVol_K_11 "校准后电柜采样电压的K值";
CM_ SG_ 2400513611 S2P_TankVol_B_11 "校准后电柜采样电压的B值（预留）";
CM_ SG_ 2400513611 S2P_TankVol_CalResult_11 "电柜采样电压校准结果反馈                              备注：高压采样k值校准结果";
CM_ SG_ 2400513612 S2P_TankVol_K_12 "校准后电柜采样电压的K值";
CM_ SG_ 2400513612 S2P_TankVol_B_12 "校准后电柜采样电压的B值（预留）";
CM_ SG_ 2400513612 S2P_TankVol_CalResult_12 "电柜采样电压校准结果反馈                              备注：高压采样k值校准结果";
CM_ SG_ 2400513613 S2P_TankVol_K_13 "校准后电柜采样电压的K值";
CM_ SG_ 2400513613 S2P_TankVol_B_13 "校准后电柜采样电压的B值（预留）";
CM_ SG_ 2400513613 S2P_TankVol_CalResult_13 "电柜采样电压校准结果反馈                              备注：高压采样k值校准结果";
CM_ SG_ 2400513614 S2P_TankVol_K_14 "校准后电柜采样电压的K值";
CM_ SG_ 2400513614 S2P_TankVol_B_14 "校准后电柜采样电压的B值（预留）";
CM_ SG_ 2400513614 S2P_TankVol_CalResult_14 "电柜采样电压校准结果反馈                              备注：高压采样k值校准结果";
CM_ SG_ 2400513615 S2P_TankVol_K_15 "校准后电柜采样电压的K值";
CM_ SG_ 2400513615 S2P_TankVol_B_15 "校准后电柜采样电压的B值（预留）";
CM_ SG_ 2400513615 S2P_TankVol_CalResult_15 "电柜采样电压校准结果反馈                              备注：高压采样k值校准结果";
CM_ SG_ 2400513616 S2P_TankVol_K_16 "校准后电柜采样电压的K值";
CM_ SG_ 2400513616 S2P_TankVol_B_16 "校准后电柜采样电压的B值（预留）";
CM_ SG_ 2400513616 S2P_TankVol_CalResult_16 "电柜采样电压校准结果反馈                              备注：高压采样k值校准结果";
CM_ SG_ 2400513617 S2P_TankVol_K_17 "校准后电柜采样电压的K值";
CM_ SG_ 2400513617 S2P_TankVol_B_17 "校准后电柜采样电压的B值（预留）";
CM_ SG_ 2400513617 S2P_TankVol_CalResult_17 "电柜采样电压校准结果反馈                              备注：高压采样k值校准结果";
CM_ SG_ 2400513618 S2P_TankVol_K_18 "校准后电柜采样电压的K值";
CM_ SG_ 2400513618 S2P_TankVol_B_18 "校准后电柜采样电压的B值（预留）";
CM_ SG_ 2400513618 S2P_TankVol_CalResult_18 "电柜采样电压校准结果反馈                              备注：高压采样k值校准结果";
CM_ SG_ 2400513619 S2P_TankVol_K_19 "校准后电柜采样电压的K值";
CM_ SG_ 2400513619 S2P_TankVol_B_19 "校准后电柜采样电压的B值（预留）";
CM_ SG_ 2400513619 S2P_TankVol_CalResult_19 "电柜采样电压校准结果反馈                              备注：高压采样k值校准结果";
CM_ SG_ 2400513620 S2P_TankVol_K_20 "校准后电柜采样电压的K值";
CM_ SG_ 2400513620 S2P_TankVol_B_20 "校准后电柜采样电压的B值（预留）";
CM_ SG_ 2400513620 S2P_TankVol_CalResult_20 "电柜采样电压校准结果反馈                              备注：高压采样k值校准结果";
CM_ SG_ 2400513621 S2P_TankVol_K_21 "校准后电柜采样电压的K值";
CM_ SG_ 2400513621 S2P_TankVol_B_21 "校准后电柜采样电压的B值（预留）";
CM_ SG_ 2400513621 S2P_TankVol_CalResult_21 "电柜采样电压校准结果反馈                              备注：高压采样k值校准结果";
CM_ SG_ 2400513622 S2P_TankVol_K_22 "校准后电柜采样电压的K值";
CM_ SG_ 2400513622 S2P_TankVol_B_22 "校准后电柜采样电压的B值（预留）";
CM_ SG_ 2400513622 S2P_TankVol_CalResult_22 "电柜采样电压校准结果反馈                              备注：高压采样k值校准结果";
CM_ SG_ 2400513623 S2P_TankVol_K_23 "校准后电柜采样电压的K值";
CM_ SG_ 2400513623 S2P_TankVol_B_23 "校准后电柜采样电压的B值（预留）";
CM_ SG_ 2400513623 S2P_TankVol_CalResult_23 "电柜采样电压校准结果反馈                              备注：高压采样k值校准结果";
CM_ SG_ 2400513624 S2P_TankVol_K_24 "校准后电柜采样电压的K值";
CM_ SG_ 2400513624 S2P_TankVol_B_24 "校准后电柜采样电压的B值（预留）";
CM_ SG_ 2400513624 S2P_TankVol_CalResult_24 "电柜采样电压校准结果反馈                              备注：高压采样k值校准结果";
CM_ SG_ 2400513625 S2P_TankVol_K_25 "校准后电柜采样电压的K值";
CM_ SG_ 2400513625 S2P_TankVol_B_25 "校准后电柜采样电压的B值（预留）";
CM_ SG_ 2400513625 S2P_TankVol_CalResult_25 "电柜采样电压校准结果反馈                              备注：高压采样k值校准结果";
CM_ SG_ 2400513626 S2P_TankVol_K_26 "校准后电柜采样电压的K值";
CM_ SG_ 2400513626 S2P_TankVol_B_26 "校准后电柜采样电压的B值（预留）";
CM_ SG_ 2400513626 S2P_TankVol_CalResult_26 "电柜采样电压校准结果反馈                              备注：高压采样k值校准结果";
CM_ SG_ 2400513627 S2P_TankVol_K_27 "校准后电柜采样电压的K值";
CM_ SG_ 2400513627 S2P_TankVol_B_27 "校准后电柜采样电压的B值（预留）";
CM_ SG_ 2400513627 S2P_TankVol_CalResult_27 "电柜采样电压校准结果反馈                              备注：高压采样k值校准结果";
CM_ SG_ 2400513628 S2P_TankVol_K_28 "校准后电柜采样电压的K值";
CM_ SG_ 2400513628 S2P_TankVol_B_28 "校准后电柜采样电压的B值（预留）";
CM_ SG_ 2400513628 S2P_TankVol_CalResult_28 "电柜采样电压校准结果反馈                              备注：高压采样k值校准结果";
CM_ SG_ 2400513629 S2P_TankVol_K_29 "校准后电柜采样电压的K值";
CM_ SG_ 2400513629 S2P_TankVol_B_29 "校准后电柜采样电压的B值（预留）";
CM_ SG_ 2400513629 S2P_TankVol_CalResult_29 "电柜采样电压校准结果反馈                              备注：高压采样k值校准结果";
CM_ SG_ 2400513630 S2P_TankVol_K_30 "校准后电柜采样电压的K值";
CM_ SG_ 2400513630 S2P_TankVol_B_30 "校准后电柜采样电压的B值（预留）";
CM_ SG_ 2400513630 S2P_TankVol_CalResult_30 "电柜采样电压校准结果反馈                              备注：高压采样k值校准结果";
CM_ SG_ 2400513631 S2P_TankVol_K_31 "校准后电柜采样电压的K值";
CM_ SG_ 2400513631 S2P_TankVol_B_31 "校准后电柜采样电压的B值（预留）";
CM_ SG_ 2400513631 S2P_TankVol_CalResult_31 "电柜采样电压校准结果反馈                              备注：高压采样k值校准结果";
CM_ SG_ 2400513632 S2P_TankVol_K_32 "校准后电柜采样电压的K值";
CM_ SG_ 2400513632 S2P_TankVol_B_32 "校准后电柜采样电压的B值（预留）";
CM_ SG_ 2400513632 S2P_TankVol_CalResult_32 "电柜采样电压校准结果反馈                              备注：高压采样k值校准结果";
CM_ SG_ 2400513633 S2P_TankVol_K_33 "校准后电柜采样电压的K值";
CM_ SG_ 2400513633 S2P_TankVol_B_33 "校准后电柜采样电压的B值（预留）";
CM_ SG_ 2400513633 S2P_TankVol_CalResult_33 "电柜采样电压校准结果反馈                              备注：高压采样k值校准结果";
CM_ SG_ 2400513634 S2P_TankVol_K_34 "校准后电柜采样电压的K值";
CM_ SG_ 2400513634 S2P_TankVol_B_34 "校准后电柜采样电压的B值（预留）";
CM_ SG_ 2400513634 S2P_TankVol_CalResult_34 "电柜采样电压校准结果反馈                              备注：高压采样k值校准结果";
CM_ SG_ 2400513635 S2P_TankVol_K_35 "校准后电柜采样电压的K值";
CM_ SG_ 2400513635 S2P_TankVol_B_35 "校准后电柜采样电压的B值（预留）";
CM_ SG_ 2400513635 S2P_TankVol_CalResult_35 "电柜采样电压校准结果反馈                              备注：高压采样k值校准结果";
CM_ SG_ 2400513636 S2P_TankVol_K_36 "校准后电柜采样电压的K值";
CM_ SG_ 2400513636 S2P_TankVol_B_36 "校准后电柜采样电压的B值（预留）";
CM_ SG_ 2400513636 S2P_TankVol_CalResult_36 "电柜采样电压校准结果反馈                              备注：高压采样k值校准结果";
CM_ SG_ 2400513637 S2P_TankVol_K_37 "校准后电柜采样电压的K值";
CM_ SG_ 2400513637 S2P_TankVol_B_37 "校准后电柜采样电压的B值（预留）";
CM_ SG_ 2400513637 S2P_TankVol_CalResult_37 "电柜采样电压校准结果反馈                              备注：高压采样k值校准结果";
CM_ SG_ 2400513638 S2P_TankVol_K_38 "校准后电柜采样电压的K值";
CM_ SG_ 2400513638 S2P_TankVol_B_38 "校准后电柜采样电压的B值（预留）";
CM_ SG_ 2400513638 S2P_TankVol_CalResult_38 "电柜采样电压校准结果反馈                              备注：高压采样k值校准结果";
CM_ SG_ 2400513639 S2P_TankVol_K_39 "校准后电柜采样电压的K值";
CM_ SG_ 2400513639 S2P_TankVol_B_39 "校准后电柜采样电压的B值（预留）";
CM_ SG_ 2400513639 S2P_TankVol_CalResult_39 "电柜采样电压校准结果反馈                              备注：高压采样k值校准结果";
CM_ SG_ 2400513640 S2P_TankVol_K_40 "校准后电柜采样电压的K值";
CM_ SG_ 2400513640 S2P_TankVol_B_40 "校准后电柜采样电压的B值（预留）";
CM_ SG_ 2400513640 S2P_TankVol_CalResult_40 "电柜采样电压校准结果反馈                              备注：高压采样k值校准结果";
CM_ SG_ 2400513641 S2P_TankVol_K_41 "校准后电柜采样电压的K值";
CM_ SG_ 2400513641 S2P_TankVol_B_41 "校准后电柜采样电压的B值（预留）";
CM_ SG_ 2400513641 S2P_TankVol_CalResult_41 "电柜采样电压校准结果反馈                              备注：高压采样k值校准结果";
CM_ SG_ 2400513642 S2P_TankVol_K_42 "校准后电柜采样电压的K值";
CM_ SG_ 2400513642 S2P_TankVol_B_42 "校准后电柜采样电压的B值（预留）";
CM_ SG_ 2400513642 S2P_TankVol_CalResult_42 "电柜采样电压校准结果反馈                              备注：高压采样k值校准结果";
CM_ SG_ 2400513643 S2P_TankVol_K_43 "校准后电柜采样电压的K值";
CM_ SG_ 2400513643 S2P_TankVol_B_43 "校准后电柜采样电压的B值（预留）";
CM_ SG_ 2400513643 S2P_TankVol_CalResult_43 "电柜采样电压校准结果反馈                              备注：高压采样k值校准结果";
CM_ SG_ 2400513644 S2P_TankVol_K_44 "校准后电柜采样电压的K值";
CM_ SG_ 2400513644 S2P_TankVol_B_44 "校准后电柜采样电压的B值（预留）";
CM_ SG_ 2400513644 S2P_TankVol_CalResult_44 "电柜采样电压校准结果反馈                              备注：高压采样k值校准结果";
CM_ SG_ 2400513645 S2P_TankVol_K_45 "校准后电柜采样电压的K值";
CM_ SG_ 2400513645 S2P_TankVol_B_45 "校准后电柜采样电压的B值（预留）";
CM_ SG_ 2400513645 S2P_TankVol_CalResult_45 "电柜采样电压校准结果反馈                              备注：高压采样k值校准结果";
CM_ SG_ 2400513646 S2P_TankVol_K_46 "校准后电柜采样电压的K值";
CM_ SG_ 2400513646 S2P_TankVol_B_46 "校准后电柜采样电压的B值（预留）";
CM_ SG_ 2400513646 S2P_TankVol_CalResult_46 "电柜采样电压校准结果反馈                              备注：高压采样k值校准结果";
CM_ SG_ 2400513647 S2P_TankVol_K_47 "校准后电柜采样电压的K值";
CM_ SG_ 2400513647 S2P_TankVol_B_47 "校准后电柜采样电压的B值（预留）";
CM_ SG_ 2400513647 S2P_TankVol_CalResult_47 "电柜采样电压校准结果反馈                              备注：高压采样k值校准结果";
CM_ SG_ 2400513648 S2P_TankVol_K_48 "校准后电柜采样电压的K值";
CM_ SG_ 2400513648 S2P_TankVol_B_48 "校准后电柜采样电压的B值（预留）";
CM_ SG_ 2400513648 S2P_TankVol_CalResult_48 "电柜采样电压校准结果反馈                              备注：高压采样k值校准结果";
CM_ SG_ 2400513649 S2P_TankVol_K_49 "校准后电柜采样电压的K值";
CM_ SG_ 2400513649 S2P_TankVol_B_49 "校准后电柜采样电压的B值（预留）";
CM_ SG_ 2400513649 S2P_TankVol_CalResult_49 "电柜采样电压校准结果反馈                              备注：高压采样k值校准结果";
CM_ SG_ 2400513650 S2P_TankVol_K_50 "校准后电柜采样电压的K值";
CM_ SG_ 2400513650 S2P_TankVol_B_50 "校准后电柜采样电压的B值（预留）";
CM_ SG_ 2400513650 S2P_TankVol_CalResult_50 "电柜采样电压校准结果反馈                              备注：高压采样k值校准结果";
CM_ SG_ 2400513651 S2P_TankVol_K_51 "校准后电柜采样电压的K值";
CM_ SG_ 2400513651 S2P_TankVol_B_51 "校准后电柜采样电压的B值（预留）";
CM_ SG_ 2400513651 S2P_TankVol_CalResult_51 "电柜采样电压校准结果反馈                              备注：高压采样k值校准结果";
CM_ SG_ 2400513652 S2P_TankVol_K_52 "校准后电柜采样电压的K值";
CM_ SG_ 2400513652 S2P_TankVol_B_52 "校准后电柜采样电压的B值（预留）";
CM_ SG_ 2400513652 S2P_TankVol_CalResult_52 "电柜采样电压校准结果反馈                              备注：高压采样k值校准结果";
CM_ SG_ 2400513653 S2P_TankVol_K_53 "校准后电柜采样电压的K值";
CM_ SG_ 2400513653 S2P_TankVol_B_53 "校准后电柜采样电压的B值（预留）";
CM_ SG_ 2400513653 S2P_TankVol_CalResult_53 "电柜采样电压校准结果反馈                              备注：高压采样k值校准结果";
CM_ SG_ 2400513654 S2P_TankVol_K_54 "校准后电柜采样电压的K值";
CM_ SG_ 2400513654 S2P_TankVol_B_54 "校准后电柜采样电压的B值（预留）";
CM_ SG_ 2400513654 S2P_TankVol_CalResult_54 "电柜采样电压校准结果反馈                              备注：高压采样k值校准结果";
CM_ SG_ 2400513655 S2P_TankVol_K_55 "校准后电柜采样电压的K值";
CM_ SG_ 2400513655 S2P_TankVol_B_55 "校准后电柜采样电压的B值（预留）";
CM_ SG_ 2400513655 S2P_TankVol_CalResult_55 "电柜采样电压校准结果反馈                              备注：高压采样k值校准结果";
CM_ SG_ 2400513656 S2P_TankVol_K_56 "校准后电柜采样电压的K值";
CM_ SG_ 2400513656 S2P_TankVol_B_56 "校准后电柜采样电压的B值（预留）";
CM_ SG_ 2400513656 S2P_TankVol_CalResult_56 "电柜采样电压校准结果反馈                              备注：高压采样k值校准结果";
CM_ SG_ 2400513657 S2P_TankVol_K_57 "校准后电柜采样电压的K值";
CM_ SG_ 2400513657 S2P_TankVol_B_57 "校准后电柜采样电压的B值（预留）";
CM_ SG_ 2400513657 S2P_TankVol_CalResult_57 "电柜采样电压校准结果反馈                              备注：高压采样k值校准结果";
CM_ SG_ 2400513658 S2P_TankVol_K_58 "校准后电柜采样电压的K值";
CM_ SG_ 2400513658 S2P_TankVol_B_58 "校准后电柜采样电压的B值（预留）";
CM_ SG_ 2400513658 S2P_TankVol_CalResult_58 "电柜采样电压校准结果反馈                              备注：高压采样k值校准结果";
CM_ SG_ 2400513659 S2P_TankVol_K_59 "校准后电柜采样电压的K值";
CM_ SG_ 2400513659 S2P_TankVol_B_59 "校准后电柜采样电压的B值（预留）";
CM_ SG_ 2400513659 S2P_TankVol_CalResult_59 "电柜采样电压校准结果反馈                              备注：高压采样k值校准结果";
CM_ SG_ 2400513660 S2P_TankVol_K_60 "校准后电柜采样电压的K值";
CM_ SG_ 2400513660 S2P_TankVol_B_60 "校准后电柜采样电压的B值（预留）";
CM_ SG_ 2400513660 S2P_TankVol_CalResult_60 "电柜采样电压校准结果反馈                              备注：高压采样k值校准结果";
CM_ SG_ 2400513661 S2P_TankVol_K_61 "校准后电柜采样电压的K值";
CM_ SG_ 2400513661 S2P_TankVol_B_61 "校准后电柜采样电压的B值（预留）";
CM_ SG_ 2400513661 S2P_TankVol_CalResult_61 "电柜采样电压校准结果反馈                              备注：高压采样k值校准结果";
CM_ SG_ 2400513662 S2P_TankVol_K_62 "校准后电柜采样电压的K值";
CM_ SG_ 2400513662 S2P_TankVol_B_62 "校准后电柜采样电压的B值（预留）";
CM_ SG_ 2400513662 S2P_TankVol_CalResult_62 "电柜采样电压校准结果反馈                              备注：高压采样k值校准结果";
CM_ SG_ 2400513663 S2P_TankVol_K_63 "校准后电柜采样电压的K值";
CM_ SG_ 2400513663 S2P_TankVol_B_63 "校准后电柜采样电压的B值（预留）";
CM_ SG_ 2400513663 S2P_TankVol_CalResult_63 "电柜采样电压校准结果反馈                              备注：高压采样k值校准结果";
CM_ SG_ 2415980097 IP_VALUE_01 "Ip Value(预留)";
CM_ SG_ 2415980097 ERROR_INDICATION_01 "Error Indication(预留)";
CM_ SG_ 2415980097 ERROR_INFORMATION_01 "Error Information(预留)";
CM_ SG_ 2415980097 VACANT_DATA_3BYTES_01 "Vacant bits(Fixed to 0)(预留)";
CM_ SG_ 2415980098 IP_VALUE_02 "Ip Value(预留)";
CM_ SG_ 2415980098 ERROR_INDICATION_02 "Error Indication(预留)";
CM_ SG_ 2415980098 ERROR_INFORMATION_02 "Error Information(预留)";
CM_ SG_ 2415980098 VACANT_DATA_3BYTES_02 "Vacant bits(Fixed to 0)(预留)";
CM_ SG_ 2415980099 IP_VALUE_03 "Ip Value(预留)";
CM_ SG_ 2415980099 ERROR_INDICATION_03 "Error Indication(预留)";
CM_ SG_ 2415980099 ERROR_INFORMATION_03 "Error Information(预留)";
CM_ SG_ 2415980099 VACANT_DATA_3BYTES_03 "Vacant bits(Fixed to 0)(预留)";
CM_ SG_ 2415980100 IP_VALUE_04 "Ip Value(预留)";
CM_ SG_ 2415980100 ERROR_INDICATION_04 "Error Indication(预留)";
CM_ SG_ 2415980100 ERROR_INFORMATION_04 "Error Information(预留)";
CM_ SG_ 2415980100 VACANT_DATA_3BYTES_04 "Vacant bits(Fixed to 0)(预留)";
CM_ SG_ 2415980101 IP_VALUE_05 "Ip Value(预留)";
CM_ SG_ 2415980101 ERROR_INDICATION_05 "Error Indication(预留)";
CM_ SG_ 2415980101 ERROR_INFORMATION_05 "Error Information(预留)";
CM_ SG_ 2415980101 VACANT_DATA_3BYTES_05 "Vacant bits(Fixed to 0)(预留)";
CM_ SG_ 2415980102 IP_VALUE_06 "Ip Value(预留)";
CM_ SG_ 2415980102 ERROR_INDICATION_06 "Error Indication(预留)";
CM_ SG_ 2415980102 ERROR_INFORMATION_06 "Error Information(预留)";
CM_ SG_ 2415980102 VACANT_DATA_3BYTES_06 "Vacant bits(Fixed to 0)(预留)";
CM_ SG_ 2415980103 IP_VALUE_07 "Ip Value(预留)";
CM_ SG_ 2415980103 ERROR_INDICATION_07 "Error Indication(预留)";
CM_ SG_ 2415980103 ERROR_INFORMATION_07 "Error Information(预留)";
CM_ SG_ 2415980103 VACANT_DATA_3BYTES_07 "Vacant bits(Fixed to 0)(预留)";
CM_ SG_ 2415980104 IP_VALUE_08 "Ip Value(预留)";
CM_ SG_ 2415980104 ERROR_INDICATION_08 "Error Indication(预留)";
CM_ SG_ 2415980104 ERROR_INFORMATION_08 "Error Information(预留)";
CM_ SG_ 2415980104 VACANT_DATA_3BYTES_08 "Vacant bits(Fixed to 0)(预留)";
CM_ SG_ 2415980105 IP_VALUE_09 "Ip Value(预留)";
CM_ SG_ 2415980105 ERROR_INDICATION_09 "Error Indication(预留)";
CM_ SG_ 2415980105 ERROR_INFORMATION_09 "Error Information(预留)";
CM_ SG_ 2415980105 VACANT_DATA_3BYTES_09 "Vacant bits(Fixed to 0)(预留)";
CM_ SG_ 2415980106 IP_VALUE_10 "Ip Value(预留)";
CM_ SG_ 2415980106 ERROR_INDICATION_10 "Error Indication(预留)";
CM_ SG_ 2415980106 ERROR_INFORMATION_10 "Error Information(预留)";
CM_ SG_ 2415980106 VACANT_DATA_3BYTES_10 "Vacant bits(Fixed to 0)(预留)";
CM_ SG_ 2415980107 IP_VALUE_11 "Ip Value(预留)";
CM_ SG_ 2415980107 ERROR_INDICATION_11 "Error Indication(预留)";
CM_ SG_ 2415980107 ERROR_INFORMATION_11 "Error Information(预留)";
CM_ SG_ 2415980107 VACANT_DATA_3BYTES_11 "Vacant bits(Fixed to 0)(预留)";
CM_ SG_ 2415980108 IP_VALUE_12 "Ip Value(预留)";
CM_ SG_ 2415980108 ERROR_INDICATION_12 "Error Indication(预留)";
CM_ SG_ 2415980108 ERROR_INFORMATION_12 "Error Information(预留)";
CM_ SG_ 2415980108 VACANT_DATA_3BYTES_12 "Vacant bits(Fixed to 0)(预留)";
CM_ SG_ 2415980109 IP_VALUE_13 "Ip Value(预留)";
CM_ SG_ 2415980109 ERROR_INDICATION_13 "Error Indication(预留)";
CM_ SG_ 2415980109 ERROR_INFORMATION_13 "Error Information(预留)";
CM_ SG_ 2415980109 VACANT_DATA_3BYTES_13 "Vacant bits(Fixed to 0)(预留)";
CM_ SG_ 2415980110 IP_VALUE_14 "Ip Value(预留)";
CM_ SG_ 2415980110 ERROR_INDICATION_14 "Error Indication(预留)";
CM_ SG_ 2415980110 ERROR_INFORMATION_14 "Error Information(预留)";
CM_ SG_ 2415980110 VACANT_DATA_3BYTES_14 "Vacant bits(Fixed to 0)(预留)";
CM_ SG_ 2415980111 IP_VALUE_15 "Ip Value(预留)";
CM_ SG_ 2415980111 ERROR_INDICATION_15 "Error Indication(预留)";
CM_ SG_ 2415980111 ERROR_INFORMATION_15 "Error Information(预留)";
CM_ SG_ 2415980111 VACANT_DATA_3BYTES_15 "Vacant bits(Fixed to 0)(预留)";
CM_ SG_ 2415980112 IP_VALUE_16 "Ip Value(预留)";
CM_ SG_ 2415980112 ERROR_INDICATION_16 "Error Indication(预留)";
CM_ SG_ 2415980112 ERROR_INFORMATION_16 "Error Information(预留)";
CM_ SG_ 2415980112 VACANT_DATA_3BYTES_16 "Vacant bits(Fixed to 0)(预留)";
CM_ SG_ 2415980113 IP_VALUE_17 "Ip Value(预留)";
CM_ SG_ 2415980113 ERROR_INDICATION_17 "Error Indication(预留)";
CM_ SG_ 2415980113 ERROR_INFORMATION_17 "Error Information(预留)";
CM_ SG_ 2415980113 VACANT_DATA_3BYTES_17 "Vacant bits(Fixed to 0)(预留)";
CM_ SG_ 2415980114 IP_VALUE_18 "Ip Value(预留)";
CM_ SG_ 2415980114 ERROR_INDICATION_18 "Error Indication(预留)";
CM_ SG_ 2415980114 ERROR_INFORMATION_18 "Error Information(预留)";
CM_ SG_ 2415980114 VACANT_DATA_3BYTES_18 "Vacant bits(Fixed to 0)(预留)";
CM_ SG_ 2415980115 IP_VALUE_19 "Ip Value(预留)";
CM_ SG_ 2415980115 ERROR_INDICATION_19 "Error Indication(预留)";
CM_ SG_ 2415980115 ERROR_INFORMATION_19 "Error Information(预留)";
CM_ SG_ 2415980115 VACANT_DATA_3BYTES_19 "Vacant bits(Fixed to 0)(预留)";
CM_ SG_ 2415980116 IP_VALUE_20 "Ip Value(预留)";
CM_ SG_ 2415980116 ERROR_INDICATION_20 "Error Indication(预留)";
CM_ SG_ 2415980116 ERROR_INFORMATION_20 "Error Information(预留)";
CM_ SG_ 2415980116 VACANT_DATA_3BYTES_20 "Vacant bits(Fixed to 0)(预留)";
CM_ SG_ 2415980117 IP_VALUE_21 "Ip Value(预留)";
CM_ SG_ 2415980117 ERROR_INDICATION_21 "Error Indication(预留)";
CM_ SG_ 2415980117 ERROR_INFORMATION_21 "Error Information(预留)";
CM_ SG_ 2415980117 VACANT_DATA_3BYTES_21 "Vacant bits(Fixed to 0)(预留)";
CM_ SG_ 2415980118 IP_VALUE_22 "Ip Value(预留)";
CM_ SG_ 2415980118 ERROR_INDICATION_22 "Error Indication(预留)";
CM_ SG_ 2415980118 ERROR_INFORMATION_22 "Error Information(预留)";
CM_ SG_ 2415980118 VACANT_DATA_3BYTES_22 "Vacant bits(Fixed to 0)(预留)";
CM_ SG_ 2415980119 IP_VALUE_23 "Ip Value(预留)";
CM_ SG_ 2415980119 ERROR_INDICATION_23 "Error Indication(预留)";
CM_ SG_ 2415980119 ERROR_INFORMATION_23 "Error Information(预留)";
CM_ SG_ 2415980119 VACANT_DATA_3BYTES_23 "Vacant bits(Fixed to 0)(预留)";
CM_ SG_ 2415980120 IP_VALUE_24 "Ip Value(预留)";
CM_ SG_ 2415980120 ERROR_INDICATION_24 "Error Indication(预留)";
CM_ SG_ 2415980120 ERROR_INFORMATION_24 "Error Information(预留)";
CM_ SG_ 2415980120 VACANT_DATA_3BYTES_24 "Vacant bits(Fixed to 0)(预留)";
CM_ SG_ 2415980121 IP_VALUE_25 "Ip Value(预留)";
CM_ SG_ 2415980121 ERROR_INDICATION_25 "Error Indication(预留)";
CM_ SG_ 2415980121 ERROR_INFORMATION_25 "Error Information(预留)";
CM_ SG_ 2415980121 VACANT_DATA_3BYTES_25 "Vacant bits(Fixed to 0)(预留)";
CM_ SG_ 2415980122 IP_VALUE_26 "Ip Value(预留)";
CM_ SG_ 2415980122 ERROR_INDICATION_26 "Error Indication(预留)";
CM_ SG_ 2415980122 ERROR_INFORMATION_26 "Error Information(预留)";
CM_ SG_ 2415980122 VACANT_DATA_3BYTES_26 "Vacant bits(Fixed to 0)(预留)";
CM_ SG_ 2415980123 IP_VALUE_27 "Ip Value(预留)";
CM_ SG_ 2415980123 ERROR_INDICATION_27 "Error Indication(预留)";
CM_ SG_ 2415980123 ERROR_INFORMATION_27 "Error Information(预留)";
CM_ SG_ 2415980123 VACANT_DATA_3BYTES_27 "Vacant bits(Fixed to 0)(预留)";
CM_ SG_ 2415980124 IP_VALUE_28 "Ip Value(预留)";
CM_ SG_ 2415980124 ERROR_INDICATION_28 "Error Indication(预留)";
CM_ SG_ 2415980124 ERROR_INFORMATION_28 "Error Information(预留)";
CM_ SG_ 2415980124 VACANT_DATA_3BYTES_28 "Vacant bits(Fixed to 0)(预留)";
CM_ SG_ 2415980125 IP_VALUE_29 "Ip Value(预留)";
CM_ SG_ 2415980125 ERROR_INDICATION_29 "Error Indication(预留)";
CM_ SG_ 2415980125 ERROR_INFORMATION_29 "Error Information(预留)";
CM_ SG_ 2415980125 VACANT_DATA_3BYTES_29 "Vacant bits(Fixed to 0)(预留)";
CM_ SG_ 2415980126 IP_VALUE_30 "Ip Value(预留)";
CM_ SG_ 2415980126 ERROR_INDICATION_30 "Error Indication(预留)";
CM_ SG_ 2415980126 ERROR_INFORMATION_30 "Error Information(预留)";
CM_ SG_ 2415980126 VACANT_DATA_3BYTES_30 "Vacant bits(Fixed to 0)(预留)";
CM_ SG_ 2415980127 IP_VALUE_31 "Ip Value(预留)";
CM_ SG_ 2415980127 ERROR_INDICATION_31 "Error Indication(预留)";
CM_ SG_ 2415980127 ERROR_INFORMATION_31 "Error Information(预留)";
CM_ SG_ 2415980127 VACANT_DATA_3BYTES_31 "Vacant bits(Fixed to 0)(预留)";
CM_ SG_ 2415980128 IP_VALUE_32 "Ip Value(预留)";
CM_ SG_ 2415980128 ERROR_INDICATION_32 "Error Indication(预留)";
CM_ SG_ 2415980128 ERROR_INFORMATION_32 "Error Information(预留)";
CM_ SG_ 2415980128 VACANT_DATA_3BYTES_32 "Vacant bits(Fixed to 0)(预留)";
CM_ SG_ 2415980129 IP_VALUE_33 "Ip Value(预留)";
CM_ SG_ 2415980129 ERROR_INDICATION_33 "Error Indication(预留)";
CM_ SG_ 2415980129 ERROR_INFORMATION_33 "Error Information(预留)";
CM_ SG_ 2415980129 VACANT_DATA_3BYTES_33 "Vacant bits(Fixed to 0)(预留)";
CM_ SG_ 2415980130 IP_VALUE_34 "Ip Value(预留)";
CM_ SG_ 2415980130 ERROR_INDICATION_34 "Error Indication(预留)";
CM_ SG_ 2415980130 ERROR_INFORMATION_34 "Error Information(预留)";
CM_ SG_ 2415980130 VACANT_DATA_3BYTES_34 "Vacant bits(Fixed to 0)(预留)";
CM_ SG_ 2415980131 IP_VALUE_35 "Ip Value(预留)";
CM_ SG_ 2415980131 ERROR_INDICATION_35 "Error Indication(预留)";
CM_ SG_ 2415980131 ERROR_INFORMATION_35 "Error Information(预留)";
CM_ SG_ 2415980131 VACANT_DATA_3BYTES_35 "Vacant bits(Fixed to 0)(预留)";
CM_ SG_ 2415980132 IP_VALUE_36 "Ip Value(预留)";
CM_ SG_ 2415980132 ERROR_INDICATION_36 "Error Indication(预留)";
CM_ SG_ 2415980132 ERROR_INFORMATION_36 "Error Information(预留)";
CM_ SG_ 2415980132 VACANT_DATA_3BYTES_36 "Vacant bits(Fixed to 0)(预留)";
CM_ SG_ 2415980133 IP_VALUE_37 "Ip Value(预留)";
CM_ SG_ 2415980133 ERROR_INDICATION_37 "Error Indication(预留)";
CM_ SG_ 2415980133 ERROR_INFORMATION_37 "Error Information(预留)";
CM_ SG_ 2415980133 VACANT_DATA_3BYTES_37 "Vacant bits(Fixed to 0)(预留)";
CM_ SG_ 2415980134 IP_VALUE_38 "Ip Value(预留)";
CM_ SG_ 2415980134 ERROR_INDICATION_38 "Error Indication(预留)";
CM_ SG_ 2415980134 ERROR_INFORMATION_38 "Error Information(预留)";
CM_ SG_ 2415980134 VACANT_DATA_3BYTES_38 "Vacant bits(Fixed to 0)(预留)";
CM_ SG_ 2415980135 IP_VALUE_39 "Ip Value(预留)";
CM_ SG_ 2415980135 ERROR_INDICATION_39 "Error Indication(预留)";
CM_ SG_ 2415980135 ERROR_INFORMATION_39 "Error Information(预留)";
CM_ SG_ 2415980135 VACANT_DATA_3BYTES_39 "Vacant bits(Fixed to 0)(预留)";
CM_ SG_ 2415980136 IP_VALUE_40 "Ip Value(预留)";
CM_ SG_ 2415980136 ERROR_INDICATION_40 "Error Indication(预留)";
CM_ SG_ 2415980136 ERROR_INFORMATION_40 "Error Information(预留)";
CM_ SG_ 2415980136 VACANT_DATA_3BYTES_40 "Vacant bits(Fixed to 0)(预留)";
CM_ SG_ 2415980137 IP_VALUE_41 "Ip Value(预留)";
CM_ SG_ 2415980137 ERROR_INDICATION_41 "Error Indication(预留)";
CM_ SG_ 2415980137 ERROR_INFORMATION_41 "Error Information(预留)";
CM_ SG_ 2415980137 VACANT_DATA_3BYTES_41 "Vacant bits(Fixed to 0)(预留)";
CM_ SG_ 2415980138 IP_VALUE_42 "Ip Value(预留)";
CM_ SG_ 2415980138 ERROR_INDICATION_42 "Error Indication(预留)";
CM_ SG_ 2415980138 ERROR_INFORMATION_42 "Error Information(预留)";
CM_ SG_ 2415980138 VACANT_DATA_3BYTES_42 "Vacant bits(Fixed to 0)(预留)";
CM_ SG_ 2415980139 IP_VALUE_43 "Ip Value(预留)";
CM_ SG_ 2415980139 ERROR_INDICATION_43 "Error Indication(预留)";
CM_ SG_ 2415980139 ERROR_INFORMATION_43 "Error Information(预留)";
CM_ SG_ 2415980139 VACANT_DATA_3BYTES_43 "Vacant bits(Fixed to 0)(预留)";
CM_ SG_ 2415980140 IP_VALUE_44 "Ip Value(预留)";
CM_ SG_ 2415980140 ERROR_INDICATION_44 "Error Indication(预留)";
CM_ SG_ 2415980140 ERROR_INFORMATION_44 "Error Information(预留)";
CM_ SG_ 2415980140 VACANT_DATA_3BYTES_44 "Vacant bits(Fixed to 0)(预留)";
CM_ SG_ 2415980141 IP_VALUE_45 "Ip Value(预留)";
CM_ SG_ 2415980141 ERROR_INDICATION_45 "Error Indication(预留)";
CM_ SG_ 2415980141 ERROR_INFORMATION_45 "Error Information(预留)";
CM_ SG_ 2415980141 VACANT_DATA_3BYTES_45 "Vacant bits(Fixed to 0)(预留)";
CM_ SG_ 2415980142 IP_VALUE_46 "Ip Value(预留)";
CM_ SG_ 2415980142 ERROR_INDICATION_46 "Error Indication(预留)";
CM_ SG_ 2415980142 ERROR_INFORMATION_46 "Error Information(预留)";
CM_ SG_ 2415980142 VACANT_DATA_3BYTES_46 "Vacant bits(Fixed to 0)(预留)";
CM_ SG_ 2415980143 IP_VALUE_47 "Ip Value(预留)";
CM_ SG_ 2415980143 ERROR_INDICATION_47 "Error Indication(预留)";
CM_ SG_ 2415980143 ERROR_INFORMATION_47 "Error Information(预留)";
CM_ SG_ 2415980143 VACANT_DATA_3BYTES_47 "Vacant bits(Fixed to 0)(预留)";
CM_ SG_ 2415980144 IP_VALUE_48 "Ip Value(预留)";
CM_ SG_ 2415980144 ERROR_INDICATION_48 "Error Indication(预留)";
CM_ SG_ 2415980144 ERROR_INFORMATION_48 "Error Information(预留)";
CM_ SG_ 2415980144 VACANT_DATA_3BYTES_48 "Vacant bits(Fixed to 0)(预留)";
CM_ SG_ 2415980145 IP_VALUE_49 "Ip Value(预留)";
CM_ SG_ 2415980145 ERROR_INDICATION_49 "Error Indication(预留)";
CM_ SG_ 2415980145 ERROR_INFORMATION_49 "Error Information(预留)";
CM_ SG_ 2415980145 VACANT_DATA_3BYTES_49 "Vacant bits(Fixed to 0)(预留)";
CM_ SG_ 2415980146 IP_VALUE_50 "Ip Value(预留)";
CM_ SG_ 2415980146 ERROR_INDICATION_50 "Error Indication(预留)";
CM_ SG_ 2415980146 ERROR_INFORMATION_50 "Error Information(预留)";
CM_ SG_ 2415980146 VACANT_DATA_3BYTES_50 "Vacant bits(Fixed to 0)(预留)";
CM_ SG_ 2415980147 IP_VALUE_51 "Ip Value(预留)";
CM_ SG_ 2415980147 ERROR_INDICATION_51 "Error Indication(预留)";
CM_ SG_ 2415980147 ERROR_INFORMATION_51 "Error Information(预留)";
CM_ SG_ 2415980147 VACANT_DATA_3BYTES_51 "Vacant bits(Fixed to 0)(预留)";
CM_ SG_ 2415980148 IP_VALUE_52 "Ip Value(预留)";
CM_ SG_ 2415980148 ERROR_INDICATION_52 "Error Indication(预留)";
CM_ SG_ 2415980148 ERROR_INFORMATION_52 "Error Information(预留)";
CM_ SG_ 2415980148 VACANT_DATA_3BYTES_52 "Vacant bits(Fixed to 0)(预留)";
CM_ SG_ 2415980149 IP_VALUE_53 "Ip Value(预留)";
CM_ SG_ 2415980149 ERROR_INDICATION_53 "Error Indication(预留)";
CM_ SG_ 2415980149 ERROR_INFORMATION_53 "Error Information(预留)";
CM_ SG_ 2415980149 VACANT_DATA_3BYTES_53 "Vacant bits(Fixed to 0)(预留)";
CM_ SG_ 2415980150 IP_VALUE_54 "Ip Value(预留)";
CM_ SG_ 2415980150 ERROR_INDICATION_54 "Error Indication(预留)";
CM_ SG_ 2415980150 ERROR_INFORMATION_54 "Error Information(预留)";
CM_ SG_ 2415980150 VACANT_DATA_3BYTES_54 "Vacant bits(Fixed to 0)(预留)";
CM_ SG_ 2415980151 IP_VALUE_55 "Ip Value(预留)";
CM_ SG_ 2415980151 ERROR_INDICATION_55 "Error Indication(预留)";
CM_ SG_ 2415980151 ERROR_INFORMATION_55 "Error Information(预留)";
CM_ SG_ 2415980151 VACANT_DATA_3BYTES_55 "Vacant bits(Fixed to 0)(预留)";
CM_ SG_ 2415980152 IP_VALUE_56 "Ip Value(预留)";
CM_ SG_ 2415980152 ERROR_INDICATION_56 "Error Indication(预留)";
CM_ SG_ 2415980152 ERROR_INFORMATION_56 "Error Information(预留)";
CM_ SG_ 2415980152 VACANT_DATA_3BYTES_56 "Vacant bits(Fixed to 0)(预留)";
CM_ SG_ 2415980153 IP_VALUE_57 "Ip Value(预留)";
CM_ SG_ 2415980153 ERROR_INDICATION_57 "Error Indication(预留)";
CM_ SG_ 2415980153 ERROR_INFORMATION_57 "Error Information(预留)";
CM_ SG_ 2415980153 VACANT_DATA_3BYTES_57 "Vacant bits(Fixed to 0)(预留)";
CM_ SG_ 2415980154 IP_VALUE_58 "Ip Value(预留)";
CM_ SG_ 2415980154 ERROR_INDICATION_58 "Error Indication(预留)";
CM_ SG_ 2415980154 ERROR_INFORMATION_58 "Error Information(预留)";
CM_ SG_ 2415980154 VACANT_DATA_3BYTES_58 "Vacant bits(Fixed to 0)(预留)";
CM_ SG_ 2415980155 IP_VALUE_59 "Ip Value(预留)";
CM_ SG_ 2415980155 ERROR_INDICATION_59 "Error Indication(预留)";
CM_ SG_ 2415980155 ERROR_INFORMATION_59 "Error Information(预留)";
CM_ SG_ 2415980155 VACANT_DATA_3BYTES_59 "Vacant bits(Fixed to 0)(预留)";
CM_ SG_ 2415980156 IP_VALUE_60 "Ip Value(预留)";
CM_ SG_ 2415980156 ERROR_INDICATION_60 "Error Indication(预留)";
CM_ SG_ 2415980156 ERROR_INFORMATION_60 "Error Information(预留)";
CM_ SG_ 2415980156 VACANT_DATA_3BYTES_60 "Vacant bits(Fixed to 0)(预留)";
CM_ SG_ 2415980157 IP_VALUE_61 "Ip Value(预留)";
CM_ SG_ 2415980157 ERROR_INDICATION_61 "Error Indication(预留)";
CM_ SG_ 2415980157 ERROR_INFORMATION_61 "Error Information(预留)";
CM_ SG_ 2415980157 VACANT_DATA_3BYTES_61 "Vacant bits(Fixed to 0)(预留)";
CM_ SG_ 2415980158 IP_VALUE_62 "Ip Value(预留)";
CM_ SG_ 2415980158 ERROR_INDICATION_62 "Error Indication(预留)";
CM_ SG_ 2415980158 ERROR_INFORMATION_62 "Error Information(预留)";
CM_ SG_ 2415980158 VACANT_DATA_3BYTES_62 "Vacant bits(Fixed to 0)(预留)";
CM_ SG_ 2415980159 IP_VALUE_63 "Ip Value(预留)";
CM_ SG_ 2415980159 ERROR_INDICATION_63 "Error Indication(预留)";
CM_ SG_ 2415980159 ERROR_INFORMATION_63 "Error Information(预留)";
CM_ SG_ 2415980159 VACANT_DATA_3BYTES_63 "Vacant bits(Fixed to 0)(预留)";
CM_ SG_ 2417487425 S2P_Bal_CSCNum_01 "CSC号";
CM_ SG_ 2417487425 S2P_Bal_CellNum_01 "CELL号";
CM_ SG_ 2417487425 S2P_Bal_Type_01 "均衡类型";
CM_ SG_ 2417487425 S2P_Bal_TimeRemain_01 "均衡剩余时间";
CM_ SG_ 2417487425 S2P_Bal_DeltaVolt_01 "均衡电芯压差";
CM_ SG_ 2417487425 S2P_Bal_CSCPowerCurr_01 "CSC电源电流";
CM_ SG_ 2417487425 S2P_Bal_TypeLevel_01 "均衡等级";
CM_ SG_ 2417487425 S2P_Bal_SystemStatus_01 "均衡条件判断";
CM_ SG_ 2417487425 S2P_Bal_Strategy_01 "均衡策略";
CM_ SG_ 2417487425 S2P_Bal_ForceBalMode_01 "强制均衡模式";
CM_ SG_ 2417487425 S2P_Bal_CellTempFault_01 "温度单点无效";
CM_ SG_ 2417487425 S2P_Bal_CellVoltFail_01 "电芯电压采样失效";
CM_ SG_ 2417487425 S2P_Bal_CloseBalInstruct_01 "其他模块关闭均衡指令";
CM_ SG_ 2417487425 S2P_Bal_CCanTimeOut_01 "CCAN通讯超时故障";
CM_ SG_ 2417487425 S2P_Bal_CellOffLine_01 "预留";
CM_ SG_ 2417487425 S2P_Bal_BalanceCircuitFault_01 "均衡回路故障";
CM_ SG_ 2417487425 S2P_Bal_CSCSourceVoltFault_01 "CSC供电电压超限";
CM_ SG_ 2417487425 S2P_Bal_CellVoltOverFault_01 "预留";
CM_ SG_ 2417487425 S2P_Bal_CellVoltLowFault_01 "预留";
CM_ SG_ 2417487425 S2P_Bal_CSCPCBTempFault_01 "预留";
CM_ SG_ 2417487425 S2P_Bal_CSCSourceCurrLowFault_01 "CSC供电电流过低，禁止放电均衡";
CM_ SG_ 2417487425 S2P_Bal_CSCSourceCurrOvrFault_01 "CSC供电电流过高，禁止充电均衡";
CM_ SG_ 2417487426 S2P_Bal_CSCNum_02 "CSC号";
CM_ SG_ 2417487426 S2P_Bal_CellNum_02 "CELL号";
CM_ SG_ 2417487426 S2P_Bal_Type_02 "均衡类型";
CM_ SG_ 2417487426 S2P_Bal_TimeRemain_02 "均衡剩余时间";
CM_ SG_ 2417487426 S2P_Bal_DeltaVolt_02 "均衡电芯压差";
CM_ SG_ 2417487426 S2P_Bal_CSCPowerCurr_02 "CSC电源电流";
CM_ SG_ 2417487426 S2P_Bal_TypeLevel_02 "均衡等级";
CM_ SG_ 2417487426 S2P_Bal_SystemStatus_02 "均衡条件判断";
CM_ SG_ 2417487426 S2P_Bal_Strategy_02 "均衡策略";
CM_ SG_ 2417487426 S2P_Bal_ForceBalMode_02 "强制均衡模式";
CM_ SG_ 2417487426 S2P_Bal_CellTempFault_02 "温度单点无效";
CM_ SG_ 2417487426 S2P_Bal_CellVoltFail_02 "电芯电压采样失效";
CM_ SG_ 2417487426 S2P_Bal_CloseBalInstruct_02 "其他模块关闭均衡指令";
CM_ SG_ 2417487426 S2P_Bal_CCanTimeOut_02 "CCAN通讯超时故障";
CM_ SG_ 2417487426 S2P_Bal_CellOffLine_02 "预留";
CM_ SG_ 2417487426 S2P_Bal_BalanceCircuitFault_02 "均衡回路故障";
CM_ SG_ 2417487426 S2P_Bal_CSCSourceVoltFault_02 "CSC供电电压超限";
CM_ SG_ 2417487426 S2P_Bal_CellVoltOverFault_02 "预留";
CM_ SG_ 2417487426 S2P_Bal_CellVoltLowFault_02 "预留";
CM_ SG_ 2417487426 S2P_Bal_CSCPCBTempFault_02 "预留";
CM_ SG_ 2417487426 S2P_Bal_CSCSourceCurrLowFault_02 "CSC供电电流过低，禁止放电均衡";
CM_ SG_ 2417487426 S2P_Bal_CSCSourceCurrOvrFault_02 "CSC供电电流过高，禁止充电均衡";
CM_ SG_ 2417487427 S2P_Bal_CSCNum_03 "CSC号";
CM_ SG_ 2417487427 S2P_Bal_CellNum_03 "CELL号";
CM_ SG_ 2417487427 S2P_Bal_Type_03 "均衡类型";
CM_ SG_ 2417487427 S2P_Bal_TimeRemain_03 "均衡剩余时间";
CM_ SG_ 2417487427 S2P_Bal_DeltaVolt_03 "均衡电芯压差";
CM_ SG_ 2417487427 S2P_Bal_CSCPowerCurr_03 "CSC电源电流";
CM_ SG_ 2417487427 S2P_Bal_TypeLevel_03 "均衡等级";
CM_ SG_ 2417487427 S2P_Bal_SystemStatus_03 "均衡条件判断";
CM_ SG_ 2417487427 S2P_Bal_Strategy_03 "均衡策略";
CM_ SG_ 2417487427 S2P_Bal_ForceBalMode_03 "强制均衡模式";
CM_ SG_ 2417487427 S2P_Bal_CellTempFault_03 "温度单点无效";
CM_ SG_ 2417487427 S2P_Bal_CellVoltFail_03 "电芯电压采样失效";
CM_ SG_ 2417487427 S2P_Bal_CloseBalInstruct_03 "其他模块关闭均衡指令";
CM_ SG_ 2417487427 S2P_Bal_CCanTimeOut_03 "CCAN通讯超时故障";
CM_ SG_ 2417487427 S2P_Bal_CellOffLine_03 "预留";
CM_ SG_ 2417487427 S2P_Bal_BalanceCircuitFault_03 "均衡回路故障";
CM_ SG_ 2417487427 S2P_Bal_CSCSourceVoltFault_03 "CSC供电电压超限";
CM_ SG_ 2417487427 S2P_Bal_CellVoltOverFault_03 "预留";
CM_ SG_ 2417487427 S2P_Bal_CellVoltLowFault_03 "预留";
CM_ SG_ 2417487427 S2P_Bal_CSCPCBTempFault_03 "预留";
CM_ SG_ 2417487427 S2P_Bal_CSCSourceCurrLowFault_03 "CSC供电电流过低，禁止放电均衡";
CM_ SG_ 2417487427 S2P_Bal_CSCSourceCurrOvrFault_03 "CSC供电电流过高，禁止充电均衡";
CM_ SG_ 2417487428 S2P_Bal_CSCNum_04 "CSC号";
CM_ SG_ 2417487428 S2P_Bal_CellNum_04 "CELL号";
CM_ SG_ 2417487428 S2P_Bal_Type_04 "均衡类型";
CM_ SG_ 2417487428 S2P_Bal_TimeRemain_04 "均衡剩余时间";
CM_ SG_ 2417487428 S2P_Bal_DeltaVolt_04 "均衡电芯压差";
CM_ SG_ 2417487428 S2P_Bal_CSCPowerCurr_04 "CSC电源电流";
CM_ SG_ 2417487428 S2P_Bal_TypeLevel_04 "均衡等级";
CM_ SG_ 2417487428 S2P_Bal_SystemStatus_04 "均衡条件判断";
CM_ SG_ 2417487428 S2P_Bal_Strategy_04 "均衡策略";
CM_ SG_ 2417487428 S2P_Bal_ForceBalMode_04 "强制均衡模式";
CM_ SG_ 2417487428 S2P_Bal_CellTempFault_04 "温度单点无效";
CM_ SG_ 2417487428 S2P_Bal_CellVoltFail_04 "电芯电压采样失效";
CM_ SG_ 2417487428 S2P_Bal_CloseBalInstruct_04 "其他模块关闭均衡指令";
CM_ SG_ 2417487428 S2P_Bal_CCanTimeOut_04 "CCAN通讯超时故障";
CM_ SG_ 2417487428 S2P_Bal_CellOffLine_04 "预留";
CM_ SG_ 2417487428 S2P_Bal_BalanceCircuitFault_04 "均衡回路故障";
CM_ SG_ 2417487428 S2P_Bal_CSCSourceVoltFault_04 "CSC供电电压超限";
CM_ SG_ 2417487428 S2P_Bal_CellVoltOverFault_04 "预留";
CM_ SG_ 2417487428 S2P_Bal_CellVoltLowFault_04 "预留";
CM_ SG_ 2417487428 S2P_Bal_CSCPCBTempFault_04 "预留";
CM_ SG_ 2417487428 S2P_Bal_CSCSourceCurrLowFault_04 "CSC供电电流过低，禁止放电均衡";
CM_ SG_ 2417487428 S2P_Bal_CSCSourceCurrOvrFault_04 "CSC供电电流过高，禁止充电均衡";
CM_ SG_ 2417487429 S2P_Bal_CSCNum_05 "CSC号";
CM_ SG_ 2417487429 S2P_Bal_CellNum_05 "CELL号";
CM_ SG_ 2417487429 S2P_Bal_Type_05 "均衡类型";
CM_ SG_ 2417487429 S2P_Bal_TimeRemain_05 "均衡剩余时间";
CM_ SG_ 2417487429 S2P_Bal_DeltaVolt_05 "均衡电芯压差";
CM_ SG_ 2417487429 S2P_Bal_CSCPowerCurr_05 "CSC电源电流";
CM_ SG_ 2417487429 S2P_Bal_TypeLevel_05 "均衡等级";
CM_ SG_ 2417487429 S2P_Bal_SystemStatus_05 "均衡条件判断";
CM_ SG_ 2417487429 S2P_Bal_Strategy_05 "均衡策略";
CM_ SG_ 2417487429 S2P_Bal_ForceBalMode_05 "强制均衡模式";
CM_ SG_ 2417487429 S2P_Bal_CellTempFault_05 "温度单点无效";
CM_ SG_ 2417487429 S2P_Bal_CellVoltFail_05 "电芯电压采样失效";
CM_ SG_ 2417487429 S2P_Bal_CloseBalInstruct_05 "其他模块关闭均衡指令";
CM_ SG_ 2417487429 S2P_Bal_CCanTimeOut_05 "CCAN通讯超时故障";
CM_ SG_ 2417487429 S2P_Bal_CellOffLine_05 "预留";
CM_ SG_ 2417487429 S2P_Bal_BalanceCircuitFault_05 "均衡回路故障";
CM_ SG_ 2417487429 S2P_Bal_CSCSourceVoltFault_05 "CSC供电电压超限";
CM_ SG_ 2417487429 S2P_Bal_CellVoltOverFault_05 "预留";
CM_ SG_ 2417487429 S2P_Bal_CellVoltLowFault_05 "预留";
CM_ SG_ 2417487429 S2P_Bal_CSCPCBTempFault_05 "预留";
CM_ SG_ 2417487429 S2P_Bal_CSCSourceCurrLowFault_05 "CSC供电电流过低，禁止放电均衡";
CM_ SG_ 2417487429 S2P_Bal_CSCSourceCurrOvrFault_05 "CSC供电电流过高，禁止充电均衡";
CM_ SG_ 2417487430 S2P_Bal_CSCNum_06 "CSC号";
CM_ SG_ 2417487430 S2P_Bal_CellNum_06 "CELL号";
CM_ SG_ 2417487430 S2P_Bal_Type_06 "均衡类型";
CM_ SG_ 2417487430 S2P_Bal_TimeRemain_06 "均衡剩余时间";
CM_ SG_ 2417487430 S2P_Bal_DeltaVolt_06 "均衡电芯压差";
CM_ SG_ 2417487430 S2P_Bal_CSCPowerCurr_06 "CSC电源电流";
CM_ SG_ 2417487430 S2P_Bal_TypeLevel_06 "均衡等级";
CM_ SG_ 2417487430 S2P_Bal_SystemStatus_06 "均衡条件判断";
CM_ SG_ 2417487430 S2P_Bal_Strategy_06 "均衡策略";
CM_ SG_ 2417487430 S2P_Bal_ForceBalMode_06 "强制均衡模式";
CM_ SG_ 2417487430 S2P_Bal_CellTempFault_06 "温度单点无效";
CM_ SG_ 2417487430 S2P_Bal_CellVoltFail_06 "电芯电压采样失效";
CM_ SG_ 2417487430 S2P_Bal_CloseBalInstruct_06 "其他模块关闭均衡指令";
CM_ SG_ 2417487430 S2P_Bal_CCanTimeOut_06 "CCAN通讯超时故障";
CM_ SG_ 2417487430 S2P_Bal_CellOffLine_06 "预留";
CM_ SG_ 2417487430 S2P_Bal_BalanceCircuitFault_06 "均衡回路故障";
CM_ SG_ 2417487430 S2P_Bal_CSCSourceVoltFault_06 "CSC供电电压超限";
CM_ SG_ 2417487430 S2P_Bal_CellVoltOverFault_06 "预留";
CM_ SG_ 2417487430 S2P_Bal_CellVoltLowFault_06 "预留";
CM_ SG_ 2417487430 S2P_Bal_CSCPCBTempFault_06 "预留";
CM_ SG_ 2417487430 S2P_Bal_CSCSourceCurrLowFault_06 "CSC供电电流过低，禁止放电均衡";
CM_ SG_ 2417487430 S2P_Bal_CSCSourceCurrOvrFault_06 "CSC供电电流过高，禁止充电均衡";
CM_ SG_ 2417487431 S2P_Bal_CSCNum_07 "CSC号";
CM_ SG_ 2417487431 S2P_Bal_CellNum_07 "CELL号";
CM_ SG_ 2417487431 S2P_Bal_Type_07 "均衡类型";
CM_ SG_ 2417487431 S2P_Bal_TimeRemain_07 "均衡剩余时间";
CM_ SG_ 2417487431 S2P_Bal_DeltaVolt_07 "均衡电芯压差";
CM_ SG_ 2417487431 S2P_Bal_CSCPowerCurr_07 "CSC电源电流";
CM_ SG_ 2417487431 S2P_Bal_TypeLevel_07 "均衡等级";
CM_ SG_ 2417487431 S2P_Bal_SystemStatus_07 "均衡条件判断";
CM_ SG_ 2417487431 S2P_Bal_Strategy_07 "均衡策略";
CM_ SG_ 2417487431 S2P_Bal_ForceBalMode_07 "强制均衡模式";
CM_ SG_ 2417487431 S2P_Bal_CellTempFault_07 "温度单点无效";
CM_ SG_ 2417487431 S2P_Bal_CellVoltFail_07 "电芯电压采样失效";
CM_ SG_ 2417487431 S2P_Bal_CloseBalInstruct_07 "其他模块关闭均衡指令";
CM_ SG_ 2417487431 S2P_Bal_CCanTimeOut_07 "CCAN通讯超时故障";
CM_ SG_ 2417487431 S2P_Bal_CellOffLine_07 "预留";
CM_ SG_ 2417487431 S2P_Bal_BalanceCircuitFault_07 "均衡回路故障";
CM_ SG_ 2417487431 S2P_Bal_CSCSourceVoltFault_07 "CSC供电电压超限";
CM_ SG_ 2417487431 S2P_Bal_CellVoltOverFault_07 "预留";
CM_ SG_ 2417487431 S2P_Bal_CellVoltLowFault_07 "预留";
CM_ SG_ 2417487431 S2P_Bal_CSCPCBTempFault_07 "预留";
CM_ SG_ 2417487431 S2P_Bal_CSCSourceCurrLowFault_07 "CSC供电电流过低，禁止放电均衡";
CM_ SG_ 2417487431 S2P_Bal_CSCSourceCurrOvrFault_07 "CSC供电电流过高，禁止充电均衡";
CM_ SG_ 2417487432 S2P_Bal_CSCNum_08 "CSC号";
CM_ SG_ 2417487432 S2P_Bal_CellNum_08 "CELL号";
CM_ SG_ 2417487432 S2P_Bal_Type_08 "均衡类型";
CM_ SG_ 2417487432 S2P_Bal_TimeRemain_08 "均衡剩余时间";
CM_ SG_ 2417487432 S2P_Bal_DeltaVolt_08 "均衡电芯压差";
CM_ SG_ 2417487432 S2P_Bal_CSCPowerCurr_08 "CSC电源电流";
CM_ SG_ 2417487432 S2P_Bal_TypeLevel_08 "均衡等级";
CM_ SG_ 2417487432 S2P_Bal_SystemStatus_08 "均衡条件判断";
CM_ SG_ 2417487432 S2P_Bal_Strategy_08 "均衡策略";
CM_ SG_ 2417487432 S2P_Bal_ForceBalMode_08 "强制均衡模式";
CM_ SG_ 2417487432 S2P_Bal_CellTempFault_08 "温度单点无效";
CM_ SG_ 2417487432 S2P_Bal_CellVoltFail_08 "电芯电压采样失效";
CM_ SG_ 2417487432 S2P_Bal_CloseBalInstruct_08 "其他模块关闭均衡指令";
CM_ SG_ 2417487432 S2P_Bal_CCanTimeOut_08 "CCAN通讯超时故障";
CM_ SG_ 2417487432 S2P_Bal_CellOffLine_08 "预留";
CM_ SG_ 2417487432 S2P_Bal_BalanceCircuitFault_08 "均衡回路故障";
CM_ SG_ 2417487432 S2P_Bal_CSCSourceVoltFault_08 "CSC供电电压超限";
CM_ SG_ 2417487432 S2P_Bal_CellVoltOverFault_08 "预留";
CM_ SG_ 2417487432 S2P_Bal_CellVoltLowFault_08 "预留";
CM_ SG_ 2417487432 S2P_Bal_CSCPCBTempFault_08 "预留";
CM_ SG_ 2417487432 S2P_Bal_CSCSourceCurrLowFault_08 "CSC供电电流过低，禁止放电均衡";
CM_ SG_ 2417487432 S2P_Bal_CSCSourceCurrOvrFault_08 "CSC供电电流过高，禁止充电均衡";
CM_ SG_ 2417487433 S2P_Bal_CSCNum_09 "CSC号";
CM_ SG_ 2417487433 S2P_Bal_CellNum_09 "CELL号";
CM_ SG_ 2417487433 S2P_Bal_Type_09 "均衡类型";
CM_ SG_ 2417487433 S2P_Bal_TimeRemain_09 "均衡剩余时间";
CM_ SG_ 2417487433 S2P_Bal_DeltaVolt_09 "均衡电芯压差";
CM_ SG_ 2417487433 S2P_Bal_CSCPowerCurr_09 "CSC电源电流";
CM_ SG_ 2417487433 S2P_Bal_TypeLevel_09 "均衡等级";
CM_ SG_ 2417487433 S2P_Bal_SystemStatus_09 "均衡条件判断";
CM_ SG_ 2417487433 S2P_Bal_Strategy_09 "均衡策略";
CM_ SG_ 2417487433 S2P_Bal_ForceBalMode_09 "强制均衡模式";
CM_ SG_ 2417487433 S2P_Bal_CellTempFault_09 "温度单点无效";
CM_ SG_ 2417487433 S2P_Bal_CellVoltFail_09 "电芯电压采样失效";
CM_ SG_ 2417487433 S2P_Bal_CloseBalInstruct_09 "其他模块关闭均衡指令";
CM_ SG_ 2417487433 S2P_Bal_CCanTimeOut_09 "CCAN通讯超时故障";
CM_ SG_ 2417487433 S2P_Bal_CellOffLine_09 "预留";
CM_ SG_ 2417487433 S2P_Bal_BalanceCircuitFault_09 "均衡回路故障";
CM_ SG_ 2417487433 S2P_Bal_CSCSourceVoltFault_09 "CSC供电电压超限";
CM_ SG_ 2417487433 S2P_Bal_CellVoltOverFault_09 "预留";
CM_ SG_ 2417487433 S2P_Bal_CellVoltLowFault_09 "预留";
CM_ SG_ 2417487433 S2P_Bal_CSCPCBTempFault_09 "预留";
CM_ SG_ 2417487433 S2P_Bal_CSCSourceCurrLowFault_09 "CSC供电电流过低，禁止放电均衡";
CM_ SG_ 2417487433 S2P_Bal_CSCSourceCurrOvrFault_09 "CSC供电电流过高，禁止充电均衡";
CM_ SG_ 2417487434 S2P_Bal_CSCNum_10 "CSC号";
CM_ SG_ 2417487434 S2P_Bal_CellNum_10 "CELL号";
CM_ SG_ 2417487434 S2P_Bal_Type_10 "均衡类型";
CM_ SG_ 2417487434 S2P_Bal_TimeRemain_10 "均衡剩余时间";
CM_ SG_ 2417487434 S2P_Bal_DeltaVolt_10 "均衡电芯压差";
CM_ SG_ 2417487434 S2P_Bal_CSCPowerCurr_10 "CSC电源电流";
CM_ SG_ 2417487434 S2P_Bal_TypeLevel_10 "均衡等级";
CM_ SG_ 2417487434 S2P_Bal_SystemStatus_10 "均衡条件判断";
CM_ SG_ 2417487434 S2P_Bal_Strategy_10 "均衡策略";
CM_ SG_ 2417487434 S2P_Bal_ForceBalMode_10 "强制均衡模式";
CM_ SG_ 2417487434 S2P_Bal_CellTempFault_10 "温度单点无效";
CM_ SG_ 2417487434 S2P_Bal_CellVoltFail_10 "电芯电压采样失效";
CM_ SG_ 2417487434 S2P_Bal_CloseBalInstruct_10 "其他模块关闭均衡指令";
CM_ SG_ 2417487434 S2P_Bal_CCanTimeOut_10 "CCAN通讯超时故障";
CM_ SG_ 2417487434 S2P_Bal_CellOffLine_10 "预留";
CM_ SG_ 2417487434 S2P_Bal_BalanceCircuitFault_10 "均衡回路故障";
CM_ SG_ 2417487434 S2P_Bal_CSCSourceVoltFault_10 "CSC供电电压超限";
CM_ SG_ 2417487434 S2P_Bal_CellVoltOverFault_10 "预留";
CM_ SG_ 2417487434 S2P_Bal_CellVoltLowFault_10 "预留";
CM_ SG_ 2417487434 S2P_Bal_CSCPCBTempFault_10 "预留";
CM_ SG_ 2417487434 S2P_Bal_CSCSourceCurrLowFault_10 "CSC供电电流过低，禁止放电均衡";
CM_ SG_ 2417487434 S2P_Bal_CSCSourceCurrOvrFault_10 "CSC供电电流过高，禁止充电均衡";
CM_ SG_ 2417487435 S2P_Bal_CSCNum_11 "CSC号";
CM_ SG_ 2417487435 S2P_Bal_CellNum_11 "CELL号";
CM_ SG_ 2417487435 S2P_Bal_Type_11 "均衡类型";
CM_ SG_ 2417487435 S2P_Bal_TimeRemain_11 "均衡剩余时间";
CM_ SG_ 2417487435 S2P_Bal_DeltaVolt_11 "均衡电芯压差";
CM_ SG_ 2417487435 S2P_Bal_CSCPowerCurr_11 "CSC电源电流";
CM_ SG_ 2417487435 S2P_Bal_TypeLevel_11 "均衡等级";
CM_ SG_ 2417487435 S2P_Bal_SystemStatus_11 "均衡条件判断";
CM_ SG_ 2417487435 S2P_Bal_Strategy_11 "均衡策略";
CM_ SG_ 2417487435 S2P_Bal_ForceBalMode_11 "强制均衡模式";
CM_ SG_ 2417487435 S2P_Bal_CellTempFault_11 "温度单点无效";
CM_ SG_ 2417487435 S2P_Bal_CellVoltFail_11 "电芯电压采样失效";
CM_ SG_ 2417487435 S2P_Bal_CloseBalInstruct_11 "其他模块关闭均衡指令";
CM_ SG_ 2417487435 S2P_Bal_CCanTimeOut_11 "CCAN通讯超时故障";
CM_ SG_ 2417487435 S2P_Bal_CellOffLine_11 "预留";
CM_ SG_ 2417487435 S2P_Bal_BalanceCircuitFault_11 "均衡回路故障";
CM_ SG_ 2417487435 S2P_Bal_CSCSourceVoltFault_11 "CSC供电电压超限";
CM_ SG_ 2417487435 S2P_Bal_CellVoltOverFault_11 "预留";
CM_ SG_ 2417487435 S2P_Bal_CellVoltLowFault_11 "预留";
CM_ SG_ 2417487435 S2P_Bal_CSCPCBTempFault_11 "预留";
CM_ SG_ 2417487435 S2P_Bal_CSCSourceCurrLowFault_11 "CSC供电电流过低，禁止放电均衡";
CM_ SG_ 2417487435 S2P_Bal_CSCSourceCurrOvrFault_11 "CSC供电电流过高，禁止充电均衡";
CM_ SG_ 2417487436 S2P_Bal_CSCNum_12 "CSC号";
CM_ SG_ 2417487436 S2P_Bal_CellNum_12 "CELL号";
CM_ SG_ 2417487436 S2P_Bal_Type_12 "均衡类型";
CM_ SG_ 2417487436 S2P_Bal_TimeRemain_12 "均衡剩余时间";
CM_ SG_ 2417487436 S2P_Bal_DeltaVolt_12 "均衡电芯压差";
CM_ SG_ 2417487436 S2P_Bal_CSCPowerCurr_12 "CSC电源电流";
CM_ SG_ 2417487436 S2P_Bal_TypeLevel_12 "均衡等级";
CM_ SG_ 2417487436 S2P_Bal_SystemStatus_12 "均衡条件判断";
CM_ SG_ 2417487436 S2P_Bal_Strategy_12 "均衡策略";
CM_ SG_ 2417487436 S2P_Bal_ForceBalMode_12 "强制均衡模式";
CM_ SG_ 2417487436 S2P_Bal_CellTempFault_12 "温度单点无效";
CM_ SG_ 2417487436 S2P_Bal_CellVoltFail_12 "电芯电压采样失效";
CM_ SG_ 2417487436 S2P_Bal_CloseBalInstruct_12 "其他模块关闭均衡指令";
CM_ SG_ 2417487436 S2P_Bal_CCanTimeOut_12 "CCAN通讯超时故障";
CM_ SG_ 2417487436 S2P_Bal_CellOffLine_12 "预留";
CM_ SG_ 2417487436 S2P_Bal_BalanceCircuitFault_12 "均衡回路故障";
CM_ SG_ 2417487436 S2P_Bal_CSCSourceVoltFault_12 "CSC供电电压超限";
CM_ SG_ 2417487436 S2P_Bal_CellVoltOverFault_12 "预留";
CM_ SG_ 2417487436 S2P_Bal_CellVoltLowFault_12 "预留";
CM_ SG_ 2417487436 S2P_Bal_CSCPCBTempFault_12 "预留";
CM_ SG_ 2417487436 S2P_Bal_CSCSourceCurrLowFault_12 "CSC供电电流过低，禁止放电均衡";
CM_ SG_ 2417487436 S2P_Bal_CSCSourceCurrOvrFault_12 "CSC供电电流过高，禁止充电均衡";
CM_ SG_ 2417487437 S2P_Bal_CSCNum_13 "CSC号";
CM_ SG_ 2417487437 S2P_Bal_CellNum_13 "CELL号";
CM_ SG_ 2417487437 S2P_Bal_Type_13 "均衡类型";
CM_ SG_ 2417487437 S2P_Bal_TimeRemain_13 "均衡剩余时间";
CM_ SG_ 2417487437 S2P_Bal_DeltaVolt_13 "均衡电芯压差";
CM_ SG_ 2417487437 S2P_Bal_CSCPowerCurr_13 "CSC电源电流";
CM_ SG_ 2417487437 S2P_Bal_TypeLevel_13 "均衡等级";
CM_ SG_ 2417487437 S2P_Bal_SystemStatus_13 "均衡条件判断";
CM_ SG_ 2417487437 S2P_Bal_Strategy_13 "均衡策略";
CM_ SG_ 2417487437 S2P_Bal_ForceBalMode_13 "强制均衡模式";
CM_ SG_ 2417487437 S2P_Bal_CellTempFault_13 "温度单点无效";
CM_ SG_ 2417487437 S2P_Bal_CellVoltFail_13 "电芯电压采样失效";
CM_ SG_ 2417487437 S2P_Bal_CloseBalInstruct_13 "其他模块关闭均衡指令";
CM_ SG_ 2417487437 S2P_Bal_CCanTimeOut_13 "CCAN通讯超时故障";
CM_ SG_ 2417487437 S2P_Bal_CellOffLine_13 "预留";
CM_ SG_ 2417487437 S2P_Bal_BalanceCircuitFault_13 "均衡回路故障";
CM_ SG_ 2417487437 S2P_Bal_CSCSourceVoltFault_13 "CSC供电电压超限";
CM_ SG_ 2417487437 S2P_Bal_CellVoltOverFault_13 "预留";
CM_ SG_ 2417487437 S2P_Bal_CellVoltLowFault_13 "预留";
CM_ SG_ 2417487437 S2P_Bal_CSCPCBTempFault_13 "预留";
CM_ SG_ 2417487437 S2P_Bal_CSCSourceCurrLowFault_13 "CSC供电电流过低，禁止放电均衡";
CM_ SG_ 2417487437 S2P_Bal_CSCSourceCurrOvrFault_13 "CSC供电电流过高，禁止充电均衡";
CM_ SG_ 2417487438 S2P_Bal_CSCNum_14 "CSC号";
CM_ SG_ 2417487438 S2P_Bal_CellNum_14 "CELL号";
CM_ SG_ 2417487438 S2P_Bal_Type_14 "均衡类型";
CM_ SG_ 2417487438 S2P_Bal_TimeRemain_14 "均衡剩余时间";
CM_ SG_ 2417487438 S2P_Bal_DeltaVolt_14 "均衡电芯压差";
CM_ SG_ 2417487438 S2P_Bal_CSCPowerCurr_14 "CSC电源电流";
CM_ SG_ 2417487438 S2P_Bal_TypeLevel_14 "均衡等级";
CM_ SG_ 2417487438 S2P_Bal_SystemStatus_14 "均衡条件判断";
CM_ SG_ 2417487438 S2P_Bal_Strategy_14 "均衡策略";
CM_ SG_ 2417487438 S2P_Bal_ForceBalMode_14 "强制均衡模式";
CM_ SG_ 2417487438 S2P_Bal_CellTempFault_14 "温度单点无效";
CM_ SG_ 2417487438 S2P_Bal_CellVoltFail_14 "电芯电压采样失效";
CM_ SG_ 2417487438 S2P_Bal_CloseBalInstruct_14 "其他模块关闭均衡指令";
CM_ SG_ 2417487438 S2P_Bal_CCanTimeOut_14 "CCAN通讯超时故障";
CM_ SG_ 2417487438 S2P_Bal_CellOffLine_14 "预留";
CM_ SG_ 2417487438 S2P_Bal_BalanceCircuitFault_14 "均衡回路故障";
CM_ SG_ 2417487438 S2P_Bal_CSCSourceVoltFault_14 "CSC供电电压超限";
CM_ SG_ 2417487438 S2P_Bal_CellVoltOverFault_14 "预留";
CM_ SG_ 2417487438 S2P_Bal_CellVoltLowFault_14 "预留";
CM_ SG_ 2417487438 S2P_Bal_CSCPCBTempFault_14 "预留";
CM_ SG_ 2417487438 S2P_Bal_CSCSourceCurrLowFault_14 "CSC供电电流过低，禁止放电均衡";
CM_ SG_ 2417487438 S2P_Bal_CSCSourceCurrOvrFault_14 "CSC供电电流过高，禁止充电均衡";
CM_ SG_ 2417487439 S2P_Bal_CSCNum_15 "CSC号";
CM_ SG_ 2417487439 S2P_Bal_CellNum_15 "CELL号";
CM_ SG_ 2417487439 S2P_Bal_Type_15 "均衡类型";
CM_ SG_ 2417487439 S2P_Bal_TimeRemain_15 "均衡剩余时间";
CM_ SG_ 2417487439 S2P_Bal_DeltaVolt_15 "均衡电芯压差";
CM_ SG_ 2417487439 S2P_Bal_CSCPowerCurr_15 "CSC电源电流";
CM_ SG_ 2417487439 S2P_Bal_TypeLevel_15 "均衡等级";
CM_ SG_ 2417487439 S2P_Bal_SystemStatus_15 "均衡条件判断";
CM_ SG_ 2417487439 S2P_Bal_Strategy_15 "均衡策略";
CM_ SG_ 2417487439 S2P_Bal_ForceBalMode_15 "强制均衡模式";
CM_ SG_ 2417487439 S2P_Bal_CellTempFault_15 "温度单点无效";
CM_ SG_ 2417487439 S2P_Bal_CellVoltFail_15 "电芯电压采样失效";
CM_ SG_ 2417487439 S2P_Bal_CloseBalInstruct_15 "其他模块关闭均衡指令";
CM_ SG_ 2417487439 S2P_Bal_CCanTimeOut_15 "CCAN通讯超时故障";
CM_ SG_ 2417487439 S2P_Bal_CellOffLine_15 "预留";
CM_ SG_ 2417487439 S2P_Bal_BalanceCircuitFault_15 "均衡回路故障";
CM_ SG_ 2417487439 S2P_Bal_CSCSourceVoltFault_15 "CSC供电电压超限";
CM_ SG_ 2417487439 S2P_Bal_CellVoltOverFault_15 "预留";
CM_ SG_ 2417487439 S2P_Bal_CellVoltLowFault_15 "预留";
CM_ SG_ 2417487439 S2P_Bal_CSCPCBTempFault_15 "预留";
CM_ SG_ 2417487439 S2P_Bal_CSCSourceCurrLowFault_15 "CSC供电电流过低，禁止放电均衡";
CM_ SG_ 2417487439 S2P_Bal_CSCSourceCurrOvrFault_15 "CSC供电电流过高，禁止充电均衡";
CM_ SG_ 2417487440 S2P_Bal_CSCNum_16 "CSC号";
CM_ SG_ 2417487440 S2P_Bal_CellNum_16 "CELL号";
CM_ SG_ 2417487440 S2P_Bal_Type_16 "均衡类型";
CM_ SG_ 2417487440 S2P_Bal_TimeRemain_16 "均衡剩余时间";
CM_ SG_ 2417487440 S2P_Bal_DeltaVolt_16 "均衡电芯压差";
CM_ SG_ 2417487440 S2P_Bal_CSCPowerCurr_16 "CSC电源电流";
CM_ SG_ 2417487440 S2P_Bal_TypeLevel_16 "均衡等级";
CM_ SG_ 2417487440 S2P_Bal_SystemStatus_16 "均衡条件判断";
CM_ SG_ 2417487440 S2P_Bal_Strategy_16 "均衡策略";
CM_ SG_ 2417487440 S2P_Bal_ForceBalMode_16 "强制均衡模式";
CM_ SG_ 2417487440 S2P_Bal_CellTempFault_16 "温度单点无效";
CM_ SG_ 2417487440 S2P_Bal_CellVoltFail_16 "电芯电压采样失效";
CM_ SG_ 2417487440 S2P_Bal_CloseBalInstruct_16 "其他模块关闭均衡指令";
CM_ SG_ 2417487440 S2P_Bal_CCanTimeOut_16 "CCAN通讯超时故障";
CM_ SG_ 2417487440 S2P_Bal_CellOffLine_16 "预留";
CM_ SG_ 2417487440 S2P_Bal_BalanceCircuitFault_16 "均衡回路故障";
CM_ SG_ 2417487440 S2P_Bal_CSCSourceVoltFault_16 "CSC供电电压超限";
CM_ SG_ 2417487440 S2P_Bal_CellVoltOverFault_16 "预留";
CM_ SG_ 2417487440 S2P_Bal_CellVoltLowFault_16 "预留";
CM_ SG_ 2417487440 S2P_Bal_CSCPCBTempFault_16 "预留";
CM_ SG_ 2417487440 S2P_Bal_CSCSourceCurrLowFault_16 "CSC供电电流过低，禁止放电均衡";
CM_ SG_ 2417487440 S2P_Bal_CSCSourceCurrOvrFault_16 "CSC供电电流过高，禁止充电均衡";
CM_ SG_ 2417487441 S2P_Bal_CSCNum_17 "CSC号";
CM_ SG_ 2417487441 S2P_Bal_CellNum_17 "CELL号";
CM_ SG_ 2417487441 S2P_Bal_Type_17 "均衡类型";
CM_ SG_ 2417487441 S2P_Bal_TimeRemain_17 "均衡剩余时间";
CM_ SG_ 2417487441 S2P_Bal_DeltaVolt_17 "均衡电芯压差";
CM_ SG_ 2417487441 S2P_Bal_CSCPowerCurr_17 "CSC电源电流";
CM_ SG_ 2417487441 S2P_Bal_TypeLevel_17 "均衡等级";
CM_ SG_ 2417487441 S2P_Bal_SystemStatus_17 "均衡条件判断";
CM_ SG_ 2417487441 S2P_Bal_Strategy_17 "均衡策略";
CM_ SG_ 2417487441 S2P_Bal_ForceBalMode_17 "强制均衡模式";
CM_ SG_ 2417487441 S2P_Bal_CellTempFault_17 "温度单点无效";
CM_ SG_ 2417487441 S2P_Bal_CellVoltFail_17 "电芯电压采样失效";
CM_ SG_ 2417487441 S2P_Bal_CloseBalInstruct_17 "其他模块关闭均衡指令";
CM_ SG_ 2417487441 S2P_Bal_CCanTimeOut_17 "CCAN通讯超时故障";
CM_ SG_ 2417487441 S2P_Bal_CellOffLine_17 "预留";
CM_ SG_ 2417487441 S2P_Bal_BalanceCircuitFault_17 "均衡回路故障";
CM_ SG_ 2417487441 S2P_Bal_CSCSourceVoltFault_17 "CSC供电电压超限";
CM_ SG_ 2417487441 S2P_Bal_CellVoltOverFault_17 "预留";
CM_ SG_ 2417487441 S2P_Bal_CellVoltLowFault_17 "预留";
CM_ SG_ 2417487441 S2P_Bal_CSCPCBTempFault_17 "预留";
CM_ SG_ 2417487441 S2P_Bal_CSCSourceCurrLowFault_17 "CSC供电电流过低，禁止放电均衡";
CM_ SG_ 2417487441 S2P_Bal_CSCSourceCurrOvrFault_17 "CSC供电电流过高，禁止充电均衡";
CM_ SG_ 2417487442 S2P_Bal_CSCNum_18 "CSC号";
CM_ SG_ 2417487442 S2P_Bal_CellNum_18 "CELL号";
CM_ SG_ 2417487442 S2P_Bal_Type_18 "均衡类型";
CM_ SG_ 2417487442 S2P_Bal_TimeRemain_18 "均衡剩余时间";
CM_ SG_ 2417487442 S2P_Bal_DeltaVolt_18 "均衡电芯压差";
CM_ SG_ 2417487442 S2P_Bal_CSCPowerCurr_18 "CSC电源电流";
CM_ SG_ 2417487442 S2P_Bal_TypeLevel_18 "均衡等级";
CM_ SG_ 2417487442 S2P_Bal_SystemStatus_18 "均衡条件判断";
CM_ SG_ 2417487442 S2P_Bal_Strategy_18 "均衡策略";
CM_ SG_ 2417487442 S2P_Bal_ForceBalMode_18 "强制均衡模式";
CM_ SG_ 2417487442 S2P_Bal_CellTempFault_18 "温度单点无效";
CM_ SG_ 2417487442 S2P_Bal_CellVoltFail_18 "电芯电压采样失效";
CM_ SG_ 2417487442 S2P_Bal_CloseBalInstruct_18 "其他模块关闭均衡指令";
CM_ SG_ 2417487442 S2P_Bal_CCanTimeOut_18 "CCAN通讯超时故障";
CM_ SG_ 2417487442 S2P_Bal_CellOffLine_18 "预留";
CM_ SG_ 2417487442 S2P_Bal_BalanceCircuitFault_18 "均衡回路故障";
CM_ SG_ 2417487442 S2P_Bal_CSCSourceVoltFault_18 "CSC供电电压超限";
CM_ SG_ 2417487442 S2P_Bal_CellVoltOverFault_18 "预留";
CM_ SG_ 2417487442 S2P_Bal_CellVoltLowFault_18 "预留";
CM_ SG_ 2417487442 S2P_Bal_CSCPCBTempFault_18 "预留";
CM_ SG_ 2417487442 S2P_Bal_CSCSourceCurrLowFault_18 "CSC供电电流过低，禁止放电均衡";
CM_ SG_ 2417487442 S2P_Bal_CSCSourceCurrOvrFault_18 "CSC供电电流过高，禁止充电均衡";
CM_ SG_ 2417487443 S2P_Bal_CSCNum_19 "CSC号";
CM_ SG_ 2417487443 S2P_Bal_CellNum_19 "CELL号";
CM_ SG_ 2417487443 S2P_Bal_Type_19 "均衡类型";
CM_ SG_ 2417487443 S2P_Bal_TimeRemain_19 "均衡剩余时间";
CM_ SG_ 2417487443 S2P_Bal_DeltaVolt_19 "均衡电芯压差";
CM_ SG_ 2417487443 S2P_Bal_CSCPowerCurr_19 "CSC电源电流";
CM_ SG_ 2417487443 S2P_Bal_TypeLevel_19 "均衡等级";
CM_ SG_ 2417487443 S2P_Bal_SystemStatus_19 "均衡条件判断";
CM_ SG_ 2417487443 S2P_Bal_Strategy_19 "均衡策略";
CM_ SG_ 2417487443 S2P_Bal_ForceBalMode_19 "强制均衡模式";
CM_ SG_ 2417487443 S2P_Bal_CellTempFault_19 "温度单点无效";
CM_ SG_ 2417487443 S2P_Bal_CellVoltFail_19 "电芯电压采样失效";
CM_ SG_ 2417487443 S2P_Bal_CloseBalInstruct_19 "其他模块关闭均衡指令";
CM_ SG_ 2417487443 S2P_Bal_CCanTimeOut_19 "CCAN通讯超时故障";
CM_ SG_ 2417487443 S2P_Bal_CellOffLine_19 "预留";
CM_ SG_ 2417487443 S2P_Bal_BalanceCircuitFault_19 "均衡回路故障";
CM_ SG_ 2417487443 S2P_Bal_CSCSourceVoltFault_19 "CSC供电电压超限";
CM_ SG_ 2417487443 S2P_Bal_CellVoltOverFault_19 "预留";
CM_ SG_ 2417487443 S2P_Bal_CellVoltLowFault_19 "预留";
CM_ SG_ 2417487443 S2P_Bal_CSCPCBTempFault_19 "预留";
CM_ SG_ 2417487443 S2P_Bal_CSCSourceCurrLowFault_19 "CSC供电电流过低，禁止放电均衡";
CM_ SG_ 2417487443 S2P_Bal_CSCSourceCurrOvrFault_19 "CSC供电电流过高，禁止充电均衡";
CM_ SG_ 2417487444 S2P_Bal_CSCNum_20 "CSC号";
CM_ SG_ 2417487444 S2P_Bal_CellNum_20 "CELL号";
CM_ SG_ 2417487444 S2P_Bal_Type_20 "均衡类型";
CM_ SG_ 2417487444 S2P_Bal_TimeRemain_20 "均衡剩余时间";
CM_ SG_ 2417487444 S2P_Bal_DeltaVolt_20 "均衡电芯压差";
CM_ SG_ 2417487444 S2P_Bal_CSCPowerCurr_20 "CSC电源电流";
CM_ SG_ 2417487444 S2P_Bal_TypeLevel_20 "均衡等级";
CM_ SG_ 2417487444 S2P_Bal_SystemStatus_20 "均衡条件判断";
CM_ SG_ 2417487444 S2P_Bal_Strategy_20 "均衡策略";
CM_ SG_ 2417487444 S2P_Bal_ForceBalMode_20 "强制均衡模式";
CM_ SG_ 2417487444 S2P_Bal_CellTempFault_20 "温度单点无效";
CM_ SG_ 2417487444 S2P_Bal_CellVoltFail_20 "电芯电压采样失效";
CM_ SG_ 2417487444 S2P_Bal_CloseBalInstruct_20 "其他模块关闭均衡指令";
CM_ SG_ 2417487444 S2P_Bal_CCanTimeOut_20 "CCAN通讯超时故障";
CM_ SG_ 2417487444 S2P_Bal_CellOffLine_20 "预留";
CM_ SG_ 2417487444 S2P_Bal_BalanceCircuitFault_20 "均衡回路故障";
CM_ SG_ 2417487444 S2P_Bal_CSCSourceVoltFault_20 "CSC供电电压超限";
CM_ SG_ 2417487444 S2P_Bal_CellVoltOverFault_20 "预留";
CM_ SG_ 2417487444 S2P_Bal_CellVoltLowFault_20 "预留";
CM_ SG_ 2417487444 S2P_Bal_CSCPCBTempFault_20 "预留";
CM_ SG_ 2417487444 S2P_Bal_CSCSourceCurrLowFault_20 "CSC供电电流过低，禁止放电均衡";
CM_ SG_ 2417487444 S2P_Bal_CSCSourceCurrOvrFault_20 "CSC供电电流过高，禁止充电均衡";
CM_ SG_ 2417487445 S2P_Bal_CSCNum_21 "CSC号";
CM_ SG_ 2417487445 S2P_Bal_CellNum_21 "CELL号";
CM_ SG_ 2417487445 S2P_Bal_Type_21 "均衡类型";
CM_ SG_ 2417487445 S2P_Bal_TimeRemain_21 "均衡剩余时间";
CM_ SG_ 2417487445 S2P_Bal_DeltaVolt_21 "均衡电芯压差";
CM_ SG_ 2417487445 S2P_Bal_CSCPowerCurr_21 "CSC电源电流";
CM_ SG_ 2417487445 S2P_Bal_TypeLevel_21 "均衡等级";
CM_ SG_ 2417487445 S2P_Bal_SystemStatus_21 "均衡条件判断";
CM_ SG_ 2417487445 S2P_Bal_Strategy_21 "均衡策略";
CM_ SG_ 2417487445 S2P_Bal_ForceBalMode_21 "强制均衡模式";
CM_ SG_ 2417487445 S2P_Bal_CellTempFault_21 "温度单点无效";
CM_ SG_ 2417487445 S2P_Bal_CellVoltFail_21 "电芯电压采样失效";
CM_ SG_ 2417487445 S2P_Bal_CloseBalInstruct_21 "其他模块关闭均衡指令";
CM_ SG_ 2417487445 S2P_Bal_CCanTimeOut_21 "CCAN通讯超时故障";
CM_ SG_ 2417487445 S2P_Bal_CellOffLine_21 "预留";
CM_ SG_ 2417487445 S2P_Bal_BalanceCircuitFault_21 "均衡回路故障";
CM_ SG_ 2417487445 S2P_Bal_CSCSourceVoltFault_21 "CSC供电电压超限";
CM_ SG_ 2417487445 S2P_Bal_CellVoltOverFault_21 "预留";
CM_ SG_ 2417487445 S2P_Bal_CellVoltLowFault_21 "预留";
CM_ SG_ 2417487445 S2P_Bal_CSCPCBTempFault_21 "预留";
CM_ SG_ 2417487445 S2P_Bal_CSCSourceCurrLowFault_21 "CSC供电电流过低，禁止放电均衡";
CM_ SG_ 2417487445 S2P_Bal_CSCSourceCurrOvrFault_21 "CSC供电电流过高，禁止充电均衡";
VAL_ 2400579193 State_Balance_Status_57 0 "forbid balance" 1 "on balance" 2 "permit balance" 3 "balancing stopped" 4 "waitting for balance" ;
VAL_ 2400579193 State_Balance_Fault_57 0 "Normal" 1 "Failure" ;
VAL_ 2400579194 State_Balance_Status_58 0 "forbid balance" 1 "on balance" 2 "permit balance" 3 "balancing stopped" 4 "waitting for balance" ;
VAL_ 2400579194 State_Balance_Fault_58 0 "Normal" 1 "Failure" ;
VAL_ 2400579195 State_Balance_Status_59 0 "forbid balance" 1 "on balance" 2 "permit balance" 3 "balancing stopped" 4 "waitting for balance" ;
VAL_ 2400579195 State_Balance_Fault_59 0 "Normal" 1 "Failure" ;
VAL_ 2400579196 State_Balance_Status_60 0 "forbid balance" 1 "on balance" 2 "permit balance" 3 "balancing stopped" 4 "waitting for balance" ;
VAL_ 2400579196 State_Balance_Fault_60 0 "Normal" 1 "Failure" ;
VAL_ 2400579197 State_Balance_Status_61 0 "forbid balance" 1 "on balance" 2 "permit balance" 3 "balancing stopped" 4 "waitting for balance" ;
VAL_ 2400579197 State_Balance_Fault_61 0 "Normal" 1 "Failure" ;
VAL_ 2400579198 State_Balance_Status_62 0 "forbid balance" 1 "on balance" 2 "permit balance" 3 "balancing stopped" 4 "waitting for balance" ;
VAL_ 2400579198 State_Balance_Fault_62 0 "Normal" 1 "Failure" ;
VAL_ 2400579199 State_Balance_Status_63 0 "forbid balance" 1 "on balance" 2 "permit balance" 3 "balancing stopped" 4 "waitting for balance" ;
VAL_ 2400579199 State_Balance_Fault_63 0 "Normal" 1 "Failure" ;
VAL_ 2400513601 S2P_TankVol_CalResult_01 0 "Invalid" 1 "Success" 2 "Failed" 3 "Invalid" ;
VAL_ 2400513602 S2P_TankVol_CalResult_02 0 "Invalid" 1 "Success" 2 "Failed" 3 "Invalid" ;
VAL_ 2400513603 S2P_TankVol_CalResult_03 0 "Invalid" 1 "Success" 2 "Failed" 3 "Invalid" ;
VAL_ 2400513604 S2P_TankVol_CalResult_04 0 "Invalid" 1 "Success" 2 "Failed" 3 "Invalid" ;
VAL_ 2400513605 S2P_TankVol_CalResult_05 0 "Invalid" 1 "Success" 2 "Failed" 3 "Invalid" ;
VAL_ 2400513606 S2P_TankVol_CalResult_06 0 "Invalid" 1 "Success" 2 "Failed" 3 "Invalid" ;
VAL_ 2400513607 S2P_TankVol_CalResult_07 0 "Invalid" 1 "Success" 2 "Failed" 3 "Invalid" ;
VAL_ 2400513608 S2P_TankVol_CalResult_08 0 "Invalid" 1 "Success" 2 "Failed" 3 "Invalid" ;
VAL_ 2400513609 S2P_TankVol_CalResult_09 0 "Invalid" 1 "Success" 2 "Failed" 3 "Invalid" ;
VAL_ 2400513610 S2P_TankVol_CalResult_10 0 "Invalid" 1 "Success" 2 "Failed" 3 "Invalid" ;
VAL_ 2400513611 S2P_TankVol_CalResult_11 0 "Invalid" 1 "Success" 2 "Failed" 3 "Invalid" ;
VAL_ 2400513612 S2P_TankVol_CalResult_12 0 "Invalid" 1 "Success" 2 "Failed" 3 "Invalid" ;
VAL_ 2400513613 S2P_TankVol_CalResult_13 0 "Invalid" 1 "Success" 2 "Failed" 3 "Invalid" ;
VAL_ 2400513614 S2P_TankVol_CalResult_14 0 "Invalid" 1 "Success" 2 "Failed" 3 "Invalid" ;
VAL_ 2400513615 S2P_TankVol_CalResult_15 0 "Invalid" 1 "Success" 2 "Failed" 3 "Invalid" ;
VAL_ 2400513616 S2P_TankVol_CalResult_16 0 "Invalid" 1 "Success" 2 "Failed" 3 "Invalid" ;
VAL_ 2400513617 S2P_TankVol_CalResult_17 0 "Invalid" 1 "Success" 2 "Failed" 3 "Invalid" ;
VAL_ 2400513618 S2P_TankVol_CalResult_18 0 "Invalid" 1 "Success" 2 "Failed" 3 "Invalid" ;
VAL_ 2400513619 S2P_TankVol_CalResult_19 0 "Invalid" 1 "Success" 2 "Failed" 3 "Invalid" ;
VAL_ 2400513620 S2P_TankVol_CalResult_20 0 "Invalid" 1 "Success" 2 "Failed" 3 "Invalid" ;
VAL_ 2400513621 S2P_TankVol_CalResult_21 0 "Invalid" 1 "Success" 2 "Failed" 3 "Invalid" ;
VAL_ 2400513622 S2P_TankVol_CalResult_22 0 "Invalid" 1 "Success" 2 "Failed" 3 "Invalid" ;
VAL_ 2400513623 S2P_TankVol_CalResult_23 0 "Invalid" 1 "Success" 2 "Failed" 3 "Invalid" ;
VAL_ 2400513624 S2P_TankVol_CalResult_24 0 "Invalid" 1 "Success" 2 "Failed" 3 "Invalid" ;
VAL_ 2400513625 S2P_TankVol_CalResult_25 0 "Invalid" 1 "Success" 2 "Failed" 3 "Invalid" ;
VAL_ 2400513626 S2P_TankVol_CalResult_26 0 "Invalid" 1 "Success" 2 "Failed" 3 "Invalid" ;
VAL_ 2400513627 S2P_TankVol_CalResult_27 0 "Invalid" 1 "Success" 2 "Failed" 3 "Invalid" ;
VAL_ 2400513628 S2P_TankVol_CalResult_28 0 "Invalid" 1 "Success" 2 "Failed" 3 "Invalid" ;
VAL_ 2400513629 S2P_TankVol_CalResult_29 0 "Invalid" 1 "Success" 2 "Failed" 3 "Invalid" ;
VAL_ 2400513630 S2P_TankVol_CalResult_30 0 "Invalid" 1 "Success" 2 "Failed" 3 "Invalid" ;
VAL_ 2400513631 S2P_TankVol_CalResult_31 0 "Invalid" 1 "Success" 2 "Failed" 3 "Invalid" ;
VAL_ 2400513632 S2P_TankVol_CalResult_32 0 "Invalid" 1 "Success" 2 "Failed" 3 "Invalid" ;
VAL_ 2400513633 S2P_TankVol_CalResult_33 0 "Invalid" 1 "Success" 2 "Failed" 3 "Invalid" ;
VAL_ 2400513634 S2P_TankVol_CalResult_34 0 "Invalid" 1 "Success" 2 "Failed" 3 "Invalid" ;
VAL_ 2400513635 S2P_TankVol_CalResult_35 0 "Invalid" 1 "Success" 2 "Failed" 3 "Invalid" ;
VAL_ 2400513636 S2P_TankVol_CalResult_36 0 "Invalid" 1 "Success" 2 "Failed" 3 "Invalid" ;
VAL_ 2400513637 S2P_TankVol_CalResult_37 0 "Invalid" 1 "Success" 2 "Failed" 3 "Invalid" ;
VAL_ 2400513638 S2P_TankVol_CalResult_38 0 "Invalid" 1 "Success" 2 "Failed" 3 "Invalid" ;
VAL_ 2400513639 S2P_TankVol_CalResult_39 0 "Invalid" 1 "Success" 2 "Failed" 3 "Invalid" ;
VAL_ 2400513640 S2P_TankVol_CalResult_40 0 "Invalid" 1 "Success" 2 "Failed" 3 "Invalid" ;
VAL_ 2400513641 S2P_TankVol_CalResult_41 0 "Invalid" 1 "Success" 2 "Failed" 3 "Invalid" ;
VAL_ 2400513642 S2P_TankVol_CalResult_42 0 "Invalid" 1 "Success" 2 "Failed" 3 "Invalid" ;
VAL_ 2400513643 S2P_TankVol_CalResult_43 0 "Invalid" 1 "Success" 2 "Failed" 3 "Invalid" ;
VAL_ 2400513644 S2P_TankVol_CalResult_44 0 "Invalid" 1 "Success" 2 "Failed" 3 "Invalid" ;
VAL_ 2400513645 S2P_TankVol_CalResult_45 0 "Invalid" 1 "Success" 2 "Failed" 3 "Invalid" ;
VAL_ 2400513646 S2P_TankVol_CalResult_46 0 "Invalid" 1 "Success" 2 "Failed" 3 "Invalid" ;
VAL_ 2400513647 S2P_TankVol_CalResult_47 0 "Invalid" 1 "Success" 2 "Failed" 3 "Invalid" ;
VAL_ 2400513648 S2P_TankVol_CalResult_48 0 "Invalid" 1 "Success" 2 "Failed" 3 "Invalid" ;
VAL_ 2400513649 S2P_TankVol_CalResult_49 0 "Invalid" 1 "Success" 2 "Failed" 3 "Invalid" ;
VAL_ 2400513650 S2P_TankVol_CalResult_50 0 "Invalid" 1 "Success" 2 "Failed" 3 "Invalid" ;
VAL_ 2400513651 S2P_TankVol_CalResult_51 0 "Invalid" 1 "Success" 2 "Failed" 3 "Invalid" ;
VAL_ 2400513652 S2P_TankVol_CalResult_52 0 "Invalid" 1 "Success" 2 "Failed" 3 "Invalid" ;
VAL_ 2400513653 S2P_TankVol_CalResult_53 0 "Invalid" 1 "Success" 2 "Failed" 3 "Invalid" ;
VAL_ 2400513654 S2P_TankVol_CalResult_54 0 "Invalid" 1 "Success" 2 "Failed" 3 "Invalid" ;
VAL_ 2400513655 S2P_TankVol_CalResult_55 0 "Invalid" 1 "Success" 2 "Failed" 3 "Invalid" ;
VAL_ 2400513656 S2P_TankVol_CalResult_56 0 "Invalid" 1 "Success" 2 "Failed" 3 "Invalid" ;
VAL_ 2400513657 S2P_TankVol_CalResult_57 0 "Invalid" 1 "Success" 2 "Failed" 3 "Invalid" ;
VAL_ 2400513658 S2P_TankVol_CalResult_58 0 "Invalid" 1 "Success" 2 "Failed" 3 "Invalid" ;
VAL_ 2400513659 S2P_TankVol_CalResult_59 0 "Invalid" 1 "Success" 2 "Failed" 3 "Invalid" ;
VAL_ 2400513660 S2P_TankVol_CalResult_60 0 "Invalid" 1 "Success" 2 "Failed" 3 "Invalid" ;
VAL_ 2400513661 S2P_TankVol_CalResult_61 0 "Invalid" 1 "Success" 2 "Failed" 3 "Invalid" ;
VAL_ 2400513662 S2P_TankVol_CalResult_62 0 "Invalid" 1 "Success" 2 "Failed" 3 "Invalid" ;
VAL_ 2400513663 S2P_TankVol_CalResult_63 0 "Invalid" 1 "Success" 2 "Failed" 3 "Invalid" ;
VAL_ 2415980097 IP_VALUE_01 -2147483648 "Failure" ;
VAL_ 2415980097 ERROR_INDICATION_01 0 "Normal" 1 "Failure" ;
VAL_ 2415980097 ERROR_INFORMATION_01 65 "Error on dataflash CRC" 66 "Fluxgate running at high frequency(<2.5kHz) for more than 10ms" 67 "Fluxgate not oscillating for more than 20ms" 68 "CAB entenred in fail safe mode" 70 "Signal not available for more than 100ms" 71 "Bridge voltage protection" ;
VAL_ 2415980098 IP_VALUE_02 -2147483648 "Failure" ;
VAL_ 2415980098 ERROR_INDICATION_02 0 "Normal" 1 "Failure" ;
VAL_ 2415980098 ERROR_INFORMATION_02 65 "Error on dataflash CRC" 66 "Fluxgate running at high frequency(<2.5kHz) for more than 10ms" 67 "Fluxgate not oscillating for more than 20ms" 68 "CAB entenred in fail safe mode" 70 "Signal not available for more than 100ms" 71 "Bridge voltage protection" ;
VAL_ 2415980099 IP_VALUE_03 -2147483648 "Failure" ;
VAL_ 2415980099 ERROR_INDICATION_03 0 "Normal" 1 "Failure" ;
VAL_ 2415980099 ERROR_INFORMATION_03 65 "Error on dataflash CRC" 66 "Fluxgate running at high frequency(<2.5kHz) for more than 10ms" 67 "Fluxgate not oscillating for more than 20ms" 68 "CAB entenred in fail safe mode" 70 "Signal not available for more than 100ms" 71 "Bridge voltage protection" ;
VAL_ 2415980100 IP_VALUE_04 -2147483648 "Failure" ;
VAL_ 2415980100 ERROR_INDICATION_04 0 "Normal" 1 "Failure" ;
VAL_ 2415980100 ERROR_INFORMATION_04 65 "Error on dataflash CRC" 66 "Fluxgate running at high frequency(<2.5kHz) for more than 10ms" 67 "Fluxgate not oscillating for more than 20ms" 68 "CAB entenred in fail safe mode" 70 "Signal not available for more than 100ms" 71 "Bridge voltage protection" ;
VAL_ 2415980101 IP_VALUE_05 -2147483648 "Failure" ;
VAL_ 2415980101 ERROR_INDICATION_05 0 "Normal" 1 "Failure" ;
VAL_ 2415980101 ERROR_INFORMATION_05 65 "Error on dataflash CRC" 66 "Fluxgate running at high frequency(<2.5kHz) for more than 10ms" 67 "Fluxgate not oscillating for more than 20ms" 68 "CAB entenred in fail safe mode" 70 "Signal not available for more than 100ms" 71 "Bridge voltage protection" ;
VAL_ 2415980102 IP_VALUE_06 -2147483648 "Failure" ;
VAL_ 2415980102 ERROR_INDICATION_06 0 "Normal" 1 "Failure" ;
VAL_ 2415980102 ERROR_INFORMATION_06 65 "Error on dataflash CRC" 66 "Fluxgate running at high frequency(<2.5kHz) for more than 10ms" 67 "Fluxgate not oscillating for more than 20ms" 68 "CAB entenred in fail safe mode" 70 "Signal not available for more than 100ms" 71 "Bridge voltage protection" ;
VAL_ 2415980103 IP_VALUE_07 -2147483648 "Failure" ;
VAL_ 2415980103 ERROR_INDICATION_07 0 "Normal" 1 "Failure" ;
VAL_ 2415980103 ERROR_INFORMATION_07 65 "Error on dataflash CRC" 66 "Fluxgate running at high frequency(<2.5kHz) for more than 10ms" 67 "Fluxgate not oscillating for more than 20ms" 68 "CAB entenred in fail safe mode" 70 "Signal not available for more than 100ms" 71 "Bridge voltage protection" ;
VAL_ 2415980104 IP_VALUE_08 -2147483648 "Failure" ;
VAL_ 2415980104 ERROR_INDICATION_08 0 "Normal" 1 "Failure" ;
VAL_ 2415980104 ERROR_INFORMATION_08 65 "Error on dataflash CRC" 66 "Fluxgate running at high frequency(<2.5kHz) for more than 10ms" 67 "Fluxgate not oscillating for more than 20ms" 68 "CAB entenred in fail safe mode" 70 "Signal not available for more than 100ms" 71 "Bridge voltage protection" ;
VAL_ 2415980105 IP_VALUE_09 -2147483648 "Failure" ;
VAL_ 2415980105 ERROR_INDICATION_09 0 "Normal" 1 "Failure" ;
VAL_ 2415980105 ERROR_INFORMATION_09 65 "Error on dataflash CRC" 66 "Fluxgate running at high frequency(<2.5kHz) for more than 10ms" 67 "Fluxgate not oscillating for more than 20ms" 68 "CAB entenred in fail safe mode" 70 "Signal not available for more than 100ms" 71 "Bridge voltage protection" ;
VAL_ 2415980106 IP_VALUE_10 -2147483648 "Failure" ;
VAL_ 2415980106 ERROR_INDICATION_10 0 "Normal" 1 "Failure" ;
VAL_ 2415980106 ERROR_INFORMATION_10 65 "Error on dataflash CRC" 66 "Fluxgate running at high frequency(<2.5kHz) for more than 10ms" 67 "Fluxgate not oscillating for more than 20ms" 68 "CAB entenred in fail safe mode" 70 "Signal not available for more than 100ms" 71 "Bridge voltage protection" ;
VAL_ 2415980107 IP_VALUE_11 -2147483648 "Failure" ;
VAL_ 2415980107 ERROR_INDICATION_11 0 "Normal" 1 "Failure" ;
VAL_ 2415980107 ERROR_INFORMATION_11 65 "Error on dataflash CRC" 66 "Fluxgate running at high frequency(<2.5kHz) for more than 10ms" 67 "Fluxgate not oscillating for more than 20ms" 68 "CAB entenred in fail safe mode" 70 "Signal not available for more than 100ms" 71 "Bridge voltage protection" ;
VAL_ 2415980108 IP_VALUE_12 -2147483648 "Failure" ;
VAL_ 2415980108 ERROR_INDICATION_12 0 "Normal" 1 "Failure" ;
VAL_ 2415980108 ERROR_INFORMATION_12 65 "Error on dataflash CRC" 66 "Fluxgate running at high frequency(<2.5kHz) for more than 10ms" 67 "Fluxgate not oscillating for more than 20ms" 68 "CAB entenred in fail safe mode" 70 "Signal not available for more than 100ms" 71 "Bridge voltage protection" ;
VAL_ 2415980109 IP_VALUE_13 -2147483648 "Failure" ;
VAL_ 2415980109 ERROR_INDICATION_13 0 "Normal" 1 "Failure" ;
VAL_ 2415980109 ERROR_INFORMATION_13 65 "Error on dataflash CRC" 66 "Fluxgate running at high frequency(<2.5kHz) for more than 10ms" 67 "Fluxgate not oscillating for more than 20ms" 68 "CAB entenred in fail safe mode" 70 "Signal not available for more than 100ms" 71 "Bridge voltage protection" ;
VAL_ 2415980110 IP_VALUE_14 -2147483648 "Failure" ;
VAL_ 2415980110 ERROR_INDICATION_14 0 "Normal" 1 "Failure" ;
VAL_ 2415980110 ERROR_INFORMATION_14 65 "Error on dataflash CRC" 66 "Fluxgate running at high frequency(<2.5kHz) for more than 10ms" 67 "Fluxgate not oscillating for more than 20ms" 68 "CAB entenred in fail safe mode" 70 "Signal not available for more than 100ms" 71 "Bridge voltage protection" ;
VAL_ 2415980111 IP_VALUE_15 -2147483648 "Failure" ;
VAL_ 2415980111 ERROR_INDICATION_15 0 "Normal" 1 "Failure" ;
VAL_ 2415980111 ERROR_INFORMATION_15 65 "Error on dataflash CRC" 66 "Fluxgate running at high frequency(<2.5kHz) for more than 10ms" 67 "Fluxgate not oscillating for more than 20ms" 68 "CAB entenred in fail safe mode" 70 "Signal not available for more than 100ms" 71 "Bridge voltage protection" ;
VAL_ 2415980112 IP_VALUE_16 -2147483648 "Failure" ;
VAL_ 2415980112 ERROR_INDICATION_16 0 "Normal" 1 "Failure" ;
VAL_ 2415980112 ERROR_INFORMATION_16 65 "Error on dataflash CRC" 66 "Fluxgate running at high frequency(<2.5kHz) for more than 10ms" 67 "Fluxgate not oscillating for more than 20ms" 68 "CAB entenred in fail safe mode" 70 "Signal not available for more than 100ms" 71 "Bridge voltage protection" ;
VAL_ 2415980113 IP_VALUE_17 -2147483648 "Failure" ;
VAL_ 2415980113 ERROR_INDICATION_17 0 "Normal" 1 "Failure" ;
VAL_ 2415980113 ERROR_INFORMATION_17 65 "Error on dataflash CRC" 66 "Fluxgate running at high frequency(<2.5kHz) for more than 10ms" 67 "Fluxgate not oscillating for more than 20ms" 68 "CAB entenred in fail safe mode" 70 "Signal not available for more than 100ms" 71 "Bridge voltage protection" ;
VAL_ 2415980114 IP_VALUE_18 -2147483648 "Failure" ;
VAL_ 2415980114 ERROR_INDICATION_18 0 "Normal" 1 "Failure" ;
VAL_ 2415980114 ERROR_INFORMATION_18 65 "Error on dataflash CRC" 66 "Fluxgate running at high frequency(<2.5kHz) for more than 10ms" 67 "Fluxgate not oscillating for more than 20ms" 68 "CAB entenred in fail safe mode" 70 "Signal not available for more than 100ms" 71 "Bridge voltage protection" ;
VAL_ 2415980115 IP_VALUE_19 -2147483648 "Failure" ;
VAL_ 2415980115 ERROR_INDICATION_19 0 "Normal" 1 "Failure" ;
VAL_ 2415980115 ERROR_INFORMATION_19 65 "Error on dataflash CRC" 66 "Fluxgate running at high frequency(<2.5kHz) for more than 10ms" 67 "Fluxgate not oscillating for more than 20ms" 68 "CAB entenred in fail safe mode" 70 "Signal not available for more than 100ms" 71 "Bridge voltage protection" ;
VAL_ 2415980116 IP_VALUE_20 -2147483648 "Failure" ;
VAL_ 2415980116 ERROR_INDICATION_20 0 "Normal" 1 "Failure" ;
VAL_ 2415980116 ERROR_INFORMATION_20 65 "Error on dataflash CRC" 66 "Fluxgate running at high frequency(<2.5kHz) for more than 10ms" 67 "Fluxgate not oscillating for more than 20ms" 68 "CAB entenred in fail safe mode" 70 "Signal not available for more than 100ms" 71 "Bridge voltage protection" ;
VAL_ 2415980117 IP_VALUE_21 -2147483648 "Failure" ;
VAL_ 2415980117 ERROR_INDICATION_21 0 "Normal" 1 "Failure" ;
VAL_ 2415980117 ERROR_INFORMATION_21 65 "Error on dataflash CRC" 66 "Fluxgate running at high frequency(<2.5kHz) for more than 10ms" 67 "Fluxgate not oscillating for more than 20ms" 68 "CAB entenred in fail safe mode" 70 "Signal not available for more than 100ms" 71 "Bridge voltage protection" ;
VAL_ 2415980118 IP_VALUE_22 -2147483648 "Failure" ;
VAL_ 2415980118 ERROR_INDICATION_22 0 "Normal" 1 "Failure" ;
VAL_ 2415980118 ERROR_INFORMATION_22 65 "Error on dataflash CRC" 66 "Fluxgate running at high frequency(<2.5kHz) for more than 10ms" 67 "Fluxgate not oscillating for more than 20ms" 68 "CAB entenred in fail safe mode" 70 "Signal not available for more than 100ms" 71 "Bridge voltage protection" ;
VAL_ 2415980119 IP_VALUE_23 -2147483648 "Failure" ;
VAL_ 2415980119 ERROR_INDICATION_23 0 "Normal" 1 "Failure" ;
VAL_ 2415980119 ERROR_INFORMATION_23 65 "Error on dataflash CRC" 66 "Fluxgate running at high frequency(<2.5kHz) for more than 10ms" 67 "Fluxgate not oscillating for more than 20ms" 68 "CAB entenred in fail safe mode" 70 "Signal not available for more than 100ms" 71 "Bridge voltage protection" ;
VAL_ 2415980120 IP_VALUE_24 -2147483648 "Failure" ;
VAL_ 2415980120 ERROR_INDICATION_24 0 "Normal" 1 "Failure" ;
VAL_ 2415980120 ERROR_INFORMATION_24 65 "Error on dataflash CRC" 66 "Fluxgate running at high frequency(<2.5kHz) for more than 10ms" 67 "Fluxgate not oscillating for more than 20ms" 68 "CAB entenred in fail safe mode" 70 "Signal not available for more than 100ms" 71 "Bridge voltage protection" ;
VAL_ 2415980121 IP_VALUE_25 -2147483648 "Failure" ;
VAL_ 2415980121 ERROR_INDICATION_25 0 "Normal" 1 "Failure" ;
VAL_ 2415980121 ERROR_INFORMATION_25 65 "Error on dataflash CRC" 66 "Fluxgate running at high frequency(<2.5kHz) for more than 10ms" 67 "Fluxgate not oscillating for more than 20ms" 68 "CAB entenred in fail safe mode" 70 "Signal not available for more than 100ms" 71 "Bridge voltage protection" ;
VAL_ 2415980122 IP_VALUE_26 -2147483648 "Failure" ;
VAL_ 2415980122 ERROR_INDICATION_26 0 "Normal" 1 "Failure" ;
VAL_ 2415980122 ERROR_INFORMATION_26 65 "Error on dataflash CRC" 66 "Fluxgate running at high frequency(<2.5kHz) for more than 10ms" 67 "Fluxgate not oscillating for more than 20ms" 68 "CAB entenred in fail safe mode" 70 "Signal not available for more than 100ms" 71 "Bridge voltage protection" ;
VAL_ 2415980123 IP_VALUE_27 -2147483648 "Failure" ;
VAL_ 2415980123 ERROR_INDICATION_27 0 "Normal" 1 "Failure" ;
VAL_ 2415980123 ERROR_INFORMATION_27 65 "Error on dataflash CRC" 66 "Fluxgate running at high frequency(<2.5kHz) for more than 10ms" 67 "Fluxgate not oscillating for more than 20ms" 68 "CAB entenred in fail safe mode" 70 "Signal not available for more than 100ms" 71 "Bridge voltage protection" ;
VAL_ 2415980124 IP_VALUE_28 -2147483648 "Failure" ;
VAL_ 2415980124 ERROR_INDICATION_28 0 "Normal" 1 "Failure" ;
VAL_ 2415980124 ERROR_INFORMATION_28 65 "Error on dataflash CRC" 66 "Fluxgate running at high frequency(<2.5kHz) for more than 10ms" 67 "Fluxgate not oscillating for more than 20ms" 68 "CAB entenred in fail safe mode" 70 "Signal not available for more than 100ms" 71 "Bridge voltage protection" ;
VAL_ 2415980125 IP_VALUE_29 -2147483648 "Failure" ;
VAL_ 2415980125 ERROR_INDICATION_29 0 "Normal" 1 "Failure" ;
VAL_ 2415980125 ERROR_INFORMATION_29 65 "Error on dataflash CRC" 66 "Fluxgate running at high frequency(<2.5kHz) for more than 10ms" 67 "Fluxgate not oscillating for more than 20ms" 68 "CAB entenred in fail safe mode" 70 "Signal not available for more than 100ms" 71 "Bridge voltage protection" ;
VAL_ 2415980126 IP_VALUE_30 -2147483648 "Failure" ;
VAL_ 2415980126 ERROR_INDICATION_30 0 "Normal" 1 "Failure" ;
VAL_ 2415980126 ERROR_INFORMATION_30 65 "Error on dataflash CRC" 66 "Fluxgate running at high frequency(<2.5kHz) for more than 10ms" 67 "Fluxgate not oscillating for more than 20ms" 68 "CAB entenred in fail safe mode" 70 "Signal not available for more than 100ms" 71 "Bridge voltage protection" ;
VAL_ 2415980127 IP_VALUE_31 -2147483648 "Failure" ;
VAL_ 2415980127 ERROR_INDICATION_31 0 "Normal" 1 "Failure" ;
VAL_ 2415980127 ERROR_INFORMATION_31 65 "Error on dataflash CRC" 66 "Fluxgate running at high frequency(<2.5kHz) for more than 10ms" 67 "Fluxgate not oscillating for more than 20ms" 68 "CAB entenred in fail safe mode" 70 "Signal not available for more than 100ms" 71 "Bridge voltage protection" ;
VAL_ 2415980128 IP_VALUE_32 -2147483648 "Failure" ;
VAL_ 2415980128 ERROR_INDICATION_32 0 "Normal" 1 "Failure" ;
VAL_ 2415980128 ERROR_INFORMATION_32 65 "Error on dataflash CRC" 66 "Fluxgate running at high frequency(<2.5kHz) for more than 10ms" 67 "Fluxgate not oscillating for more than 20ms" 68 "CAB entenred in fail safe mode" 70 "Signal not available for more than 100ms" 71 "Bridge voltage protection" ;
VAL_ 2415980129 IP_VALUE_33 -2147483648 "Failure" ;
VAL_ 2415980129 ERROR_INDICATION_33 0 "Normal" 1 "Failure" ;
VAL_ 2415980129 ERROR_INFORMATION_33 65 "Error on dataflash CRC" 66 "Fluxgate running at high frequency(<2.5kHz) for more than 10ms" 67 "Fluxgate not oscillating for more than 20ms" 68 "CAB entenred in fail safe mode" 70 "Signal not available for more than 100ms" 71 "Bridge voltage protection" ;
VAL_ 2415980130 IP_VALUE_34 -2147483648 "Failure" ;
VAL_ 2415980130 ERROR_INDICATION_34 0 "Normal" 1 "Failure" ;
VAL_ 2415980130 ERROR_INFORMATION_34 65 "Error on dataflash CRC" 66 "Fluxgate running at high frequency(<2.5kHz) for more than 10ms" 67 "Fluxgate not oscillating for more than 20ms" 68 "CAB entenred in fail safe mode" 70 "Signal not available for more than 100ms" 71 "Bridge voltage protection" ;
VAL_ 2415980131 IP_VALUE_35 -2147483648 "Failure" ;
VAL_ 2415980131 ERROR_INDICATION_35 0 "Normal" 1 "Failure" ;
VAL_ 2415980131 ERROR_INFORMATION_35 65 "Error on dataflash CRC" 66 "Fluxgate running at high frequency(<2.5kHz) for more than 10ms" 67 "Fluxgate not oscillating for more than 20ms" 68 "CAB entenred in fail safe mode" 70 "Signal not available for more than 100ms" 71 "Bridge voltage protection" ;
VAL_ 2415980132 IP_VALUE_36 -2147483648 "Failure" ;
VAL_ 2415980132 ERROR_INDICATION_36 0 "Normal" 1 "Failure" ;
VAL_ 2415980132 ERROR_INFORMATION_36 65 "Error on dataflash CRC" 66 "Fluxgate running at high frequency(<2.5kHz) for more than 10ms" 67 "Fluxgate not oscillating for more than 20ms" 68 "CAB entenred in fail safe mode" 70 "Signal not available for more than 100ms" 71 "Bridge voltage protection" ;
VAL_ 2415980133 IP_VALUE_37 -2147483648 "Failure" ;
VAL_ 2415980133 ERROR_INDICATION_37 0 "Normal" 1 "Failure" ;
VAL_ 2415980133 ERROR_INFORMATION_37 65 "Error on dataflash CRC" 66 "Fluxgate running at high frequency(<2.5kHz) for more than 10ms" 67 "Fluxgate not oscillating for more than 20ms" 68 "CAB entenred in fail safe mode" 70 "Signal not available for more than 100ms" 71 "Bridge voltage protection" ;
VAL_ 2415980134 IP_VALUE_38 -2147483648 "Failure" ;
VAL_ 2415980134 ERROR_INDICATION_38 0 "Normal" 1 "Failure" ;
VAL_ 2415980134 ERROR_INFORMATION_38 65 "Error on dataflash CRC" 66 "Fluxgate running at high frequency(<2.5kHz) for more than 10ms" 67 "Fluxgate not oscillating for more than 20ms" 68 "CAB entenred in fail safe mode" 70 "Signal not available for more than 100ms" 71 "Bridge voltage protection" ;
VAL_ 2415980135 IP_VALUE_39 -2147483648 "Failure" ;
VAL_ 2415980135 ERROR_INDICATION_39 0 "Normal" 1 "Failure" ;
VAL_ 2415980135 ERROR_INFORMATION_39 65 "Error on dataflash CRC" 66 "Fluxgate running at high frequency(<2.5kHz) for more than 10ms" 67 "Fluxgate not oscillating for more than 20ms" 68 "CAB entenred in fail safe mode" 70 "Signal not available for more than 100ms" 71 "Bridge voltage protection" ;
VAL_ 2415980136 IP_VALUE_40 -2147483648 "Failure" ;
VAL_ 2415980136 ERROR_INDICATION_40 0 "Normal" 1 "Failure" ;
VAL_ 2415980136 ERROR_INFORMATION_40 65 "Error on dataflash CRC" 66 "Fluxgate running at high frequency(<2.5kHz) for more than 10ms" 67 "Fluxgate not oscillating for more than 20ms" 68 "CAB entenred in fail safe mode" 70 "Signal not available for more than 100ms" 71 "Bridge voltage protection" ;
VAL_ 2415980137 IP_VALUE_41 -2147483648 "Failure" ;
VAL_ 2415980137 ERROR_INDICATION_41 0 "Normal" 1 "Failure" ;
VAL_ 2415980137 ERROR_INFORMATION_41 65 "Error on dataflash CRC" 66 "Fluxgate running at high frequency(<2.5kHz) for more than 10ms" 67 "Fluxgate not oscillating for more than 20ms" 68 "CAB entenred in fail safe mode" 70 "Signal not available for more than 100ms" 71 "Bridge voltage protection" ;
VAL_ 2415980138 IP_VALUE_42 -2147483648 "Failure" ;
VAL_ 2415980138 ERROR_INDICATION_42 0 "Normal" 1 "Failure" ;
VAL_ 2415980138 ERROR_INFORMATION_42 65 "Error on dataflash CRC" 66 "Fluxgate running at high frequency(<2.5kHz) for more than 10ms" 67 "Fluxgate not oscillating for more than 20ms" 68 "CAB entenred in fail safe mode" 70 "Signal not available for more than 100ms" 71 "Bridge voltage protection" ;
VAL_ 2415980139 IP_VALUE_43 -2147483648 "Failure" ;
VAL_ 2415980139 ERROR_INDICATION_43 0 "Normal" 1 "Failure" ;
VAL_ 2415980139 ERROR_INFORMATION_43 65 "Error on dataflash CRC" 66 "Fluxgate running at high frequency(<2.5kHz) for more than 10ms" 67 "Fluxgate not oscillating for more than 20ms" 68 "CAB entenred in fail safe mode" 70 "Signal not available for more than 100ms" 71 "Bridge voltage protection" ;
VAL_ 2415980140 IP_VALUE_44 -2147483648 "Failure" ;
VAL_ 2415980140 ERROR_INDICATION_44 0 "Normal" 1 "Failure" ;
VAL_ 2415980140 ERROR_INFORMATION_44 65 "Error on dataflash CRC" 66 "Fluxgate running at high frequency(<2.5kHz) for more than 10ms" 67 "Fluxgate not oscillating for more than 20ms" 68 "CAB entenred in fail safe mode" 70 "Signal not available for more than 100ms" 71 "Bridge voltage protection" ;
VAL_ 2415980141 IP_VALUE_45 -2147483648 "Failure" ;
VAL_ 2415980141 ERROR_INDICATION_45 0 "Normal" 1 "Failure" ;
VAL_ 2415980141 ERROR_INFORMATION_45 65 "Error on dataflash CRC" 66 "Fluxgate running at high frequency(<2.5kHz) for more than 10ms" 67 "Fluxgate not oscillating for more than 20ms" 68 "CAB entenred in fail safe mode" 70 "Signal not available for more than 100ms" 71 "Bridge voltage protection" ;
VAL_ 2415980142 IP_VALUE_46 -2147483648 "Failure" ;
VAL_ 2415980142 ERROR_INDICATION_46 0 "Normal" 1 "Failure" ;
VAL_ 2415980142 ERROR_INFORMATION_46 65 "Error on dataflash CRC" 66 "Fluxgate running at high frequency(<2.5kHz) for more than 10ms" 67 "Fluxgate not oscillating for more than 20ms" 68 "CAB entenred in fail safe mode" 70 "Signal not available for more than 100ms" 71 "Bridge voltage protection" ;
VAL_ 2415980143 IP_VALUE_47 -2147483648 "Failure" ;
VAL_ 2415980143 ERROR_INDICATION_47 0 "Normal" 1 "Failure" ;
VAL_ 2415980143 ERROR_INFORMATION_47 65 "Error on dataflash CRC" 66 "Fluxgate running at high frequency(<2.5kHz) for more than 10ms" 67 "Fluxgate not oscillating for more than 20ms" 68 "CAB entenred in fail safe mode" 70 "Signal not available for more than 100ms" 71 "Bridge voltage protection" ;
VAL_ 2415980144 IP_VALUE_48 -2147483648 "Failure" ;
VAL_ 2415980144 ERROR_INDICATION_48 0 "Normal" 1 "Failure" ;
VAL_ 2415980144 ERROR_INFORMATION_48 65 "Error on dataflash CRC" 66 "Fluxgate running at high frequency(<2.5kHz) for more than 10ms" 67 "Fluxgate not oscillating for more than 20ms" 68 "CAB entenred in fail safe mode" 70 "Signal not available for more than 100ms" 71 "Bridge voltage protection" ;
VAL_ 2415980145 IP_VALUE_49 -2147483648 "Failure" ;
VAL_ 2415980145 ERROR_INDICATION_49 0 "Normal" 1 "Failure" ;
VAL_ 2415980145 ERROR_INFORMATION_49 65 "Error on dataflash CRC" 66 "Fluxgate running at high frequency(<2.5kHz) for more than 10ms" 67 "Fluxgate not oscillating for more than 20ms" 68 "CAB entenred in fail safe mode" 70 "Signal not available for more than 100ms" 71 "Bridge voltage protection" ;
VAL_ 2415980146 IP_VALUE_50 -2147483648 "Failure" ;
VAL_ 2415980146 ERROR_INDICATION_50 0 "Normal" 1 "Failure" ;
VAL_ 2415980146 ERROR_INFORMATION_50 65 "Error on dataflash CRC" 66 "Fluxgate running at high frequency(<2.5kHz) for more than 10ms" 67 "Fluxgate not oscillating for more than 20ms" 68 "CAB entenred in fail safe mode" 70 "Signal not available for more than 100ms" 71 "Bridge voltage protection" ;
VAL_ 2415980147 IP_VALUE_51 -2147483648 "Failure" ;
VAL_ 2415980147 ERROR_INDICATION_51 0 "Normal" 1 "Failure" ;
VAL_ 2415980147 ERROR_INFORMATION_51 65 "Error on dataflash CRC" 66 "Fluxgate running at high frequency(<2.5kHz) for more than 10ms" 67 "Fluxgate not oscillating for more than 20ms" 68 "CAB entenred in fail safe mode" 70 "Signal not available for more than 100ms" 71 "Bridge voltage protection" ;
VAL_ 2415980148 IP_VALUE_52 -2147483648 "Failure" ;
VAL_ 2415980148 ERROR_INDICATION_52 0 "Normal" 1 "Failure" ;
VAL_ 2415980148 ERROR_INFORMATION_52 65 "Error on dataflash CRC" 66 "Fluxgate running at high frequency(<2.5kHz) for more than 10ms" 67 "Fluxgate not oscillating for more than 20ms" 68 "CAB entenred in fail safe mode" 70 "Signal not available for more than 100ms" 71 "Bridge voltage protection" ;
VAL_ 2415980149 IP_VALUE_53 -2147483648 "Failure" ;
VAL_ 2415980149 ERROR_INDICATION_53 0 "Normal" 1 "Failure" ;
VAL_ 2415980149 ERROR_INFORMATION_53 65 "Error on dataflash CRC" 66 "Fluxgate running at high frequency(<2.5kHz) for more than 10ms" 67 "Fluxgate not oscillating for more than 20ms" 68 "CAB entenred in fail safe mode" 70 "Signal not available for more than 100ms" 71 "Bridge voltage protection" ;
VAL_ 2415980150 IP_VALUE_54 -2147483648 "Failure" ;
VAL_ 2415980150 ERROR_INDICATION_54 0 "Normal" 1 "Failure" ;
VAL_ 2415980150 ERROR_INFORMATION_54 65 "Error on dataflash CRC" 66 "Fluxgate running at high frequency(<2.5kHz) for more than 10ms" 67 "Fluxgate not oscillating for more than 20ms" 68 "CAB entenred in fail safe mode" 70 "Signal not available for more than 100ms" 71 "Bridge voltage protection" ;
VAL_ 2415980151 IP_VALUE_55 -2147483648 "Failure" ;
VAL_ 2415980151 ERROR_INDICATION_55 0 "Normal" 1 "Failure" ;
VAL_ 2415980151 ERROR_INFORMATION_55 65 "Error on dataflash CRC" 66 "Fluxgate running at high frequency(<2.5kHz) for more than 10ms" 67 "Fluxgate not oscillating for more than 20ms" 68 "CAB entenred in fail safe mode" 70 "Signal not available for more than 100ms" 71 "Bridge voltage protection" ;
VAL_ 2415980152 IP_VALUE_56 -2147483648 "Failure" ;
VAL_ 2415980152 ERROR_INDICATION_56 0 "Normal" 1 "Failure" ;
VAL_ 2415980152 ERROR_INFORMATION_56 65 "Error on dataflash CRC" 66 "Fluxgate running at high frequency(<2.5kHz) for more than 10ms" 67 "Fluxgate not oscillating for more than 20ms" 68 "CAB entenred in fail safe mode" 70 "Signal not available for more than 100ms" 71 "Bridge voltage protection" ;
VAL_ 2415980153 IP_VALUE_57 -2147483648 "Failure" ;
VAL_ 2415980153 ERROR_INDICATION_57 0 "Normal" 1 "Failure" ;
VAL_ 2415980153 ERROR_INFORMATION_57 65 "Error on dataflash CRC" 66 "Fluxgate running at high frequency(<2.5kHz) for more than 10ms" 67 "Fluxgate not oscillating for more than 20ms" 68 "CAB entenred in fail safe mode" 70 "Signal not available for more than 100ms" 71 "Bridge voltage protection" ;
VAL_ 2415980154 IP_VALUE_58 -2147483648 "Failure" ;
VAL_ 2415980154 ERROR_INDICATION_58 0 "Normal" 1 "Failure" ;
VAL_ 2415980154 ERROR_INFORMATION_58 65 "Error on dataflash CRC" 66 "Fluxgate running at high frequency(<2.5kHz) for more than 10ms" 67 "Fluxgate not oscillating for more than 20ms" 68 "CAB entenred in fail safe mode" 70 "Signal not available for more than 100ms" 71 "Bridge voltage protection" ;
VAL_ 2415980155 IP_VALUE_59 -2147483648 "Failure" ;
VAL_ 2415980155 ERROR_INDICATION_59 0 "Normal" 1 "Failure" ;
VAL_ 2415980155 ERROR_INFORMATION_59 65 "Error on dataflash CRC" 66 "Fluxgate running at high frequency(<2.5kHz) for more than 10ms" 67 "Fluxgate not oscillating for more than 20ms" 68 "CAB entenred in fail safe mode" 70 "Signal not available for more than 100ms" 71 "Bridge voltage protection" ;
VAL_ 2415980156 IP_VALUE_60 -2147483648 "Failure" ;
VAL_ 2415980156 ERROR_INDICATION_60 0 "Normal" 1 "Failure" ;
VAL_ 2415980156 ERROR_INFORMATION_60 65 "Error on dataflash CRC" 66 "Fluxgate running at high frequency(<2.5kHz) for more than 10ms" 67 "Fluxgate not oscillating for more than 20ms" 68 "CAB entenred in fail safe mode" 70 "Signal not available for more than 100ms" 71 "Bridge voltage protection" ;
VAL_ 2415980157 IP_VALUE_61 -2147483648 "Failure" ;
VAL_ 2415980157 ERROR_INDICATION_61 0 "Normal" 1 "Failure" ;
VAL_ 2415980157 ERROR_INFORMATION_61 65 "Error on dataflash CRC" 66 "Fluxgate running at high frequency(<2.5kHz) for more than 10ms" 67 "Fluxgate not oscillating for more than 20ms" 68 "CAB entenred in fail safe mode" 70 "Signal not available for more than 100ms" 71 "Bridge voltage protection" ;
VAL_ 2415980158 IP_VALUE_62 -2147483648 "Failure" ;
VAL_ 2415980158 ERROR_INDICATION_62 0 "Normal" 1 "Failure" ;
VAL_ 2415980158 ERROR_INFORMATION_62 65 "Error on dataflash CRC" 66 "Fluxgate running at high frequency(<2.5kHz) for more than 10ms" 67 "Fluxgate not oscillating for more than 20ms" 68 "CAB entenred in fail safe mode" 70 "Signal not available for more than 100ms" 71 "Bridge voltage protection" ;
VAL_ 2415980159 IP_VALUE_63 -2147483648 "Failure" ;
VAL_ 2415980159 ERROR_INDICATION_63 0 "Normal" 1 "Failure" ;
VAL_ 2415980159 ERROR_INFORMATION_63 65 "Error on dataflash CRC" 66 "Fluxgate running at high frequency(<2.5kHz) for more than 10ms" 67 "Fluxgate not oscillating for more than 20ms" 68 "CAB entenred in fail safe mode" 70 "Signal not available for more than 100ms" 71 "Bridge voltage protection" ;
VAL_ 2417487425 S2P_Bal_CSCNum_01 0 "No CSC" 1 "CSC 1" 2 "CSC 2" 3 "CSC 3" 4 "CSC 4" 5 "CSC 5" 6 "CSC 6" 7 "CSC 7" 8 "CSC 8" 9 "CSC 9" 10 "CSC 10" 11 "CSC 11" 12 "CSC 12" 13 "CSC 13" 14 "CSC 14" 15 "CSC 15" 16 "CSC 16" 17 "CSC 17" 18 "CSC 18" 19 "CSC 19" 20 "CSC 20" 21 "CSC 21" 22 "CSC 22" 23 "CSC 23" 24 "CSC 24" 25 "CSC 25" 26 "CSC 26" 27 "CSC 27" 28 "CSC 28" 29 "CSC 29" 30 "CSC 30" 31 "CSC 31" ;
VAL_ 2417487425 S2P_Bal_CellNum_01 1 "Cell 1" 2 "Cell 2" 3 "Cell 3" 4 "Cell 4" 5 "Cell 5" 6 "Cell 6" 7 "Cell 7" 8 "Cell 8" 9 "Cell 9" 10 "Cell 10" 11 "Cell 11" 12 "Cell 12" 13 "Cell 13" 14 "Cell 14" 15 "Cell 15" 16 "Cell 16" 63 "Null" ;
VAL_ 2417487425 S2P_Bal_Type_01 0 "Balance stop" 1 "charge Balance" 2 "discharge Balance" ;
VAL_ 2417487425 S2P_Bal_TypeLevel_01 0 "Not Balance" 1 "Low end Balance" 2 "High end Balance" 3 "Force Balance" ;
VAL_ 2417487425 S2P_Bal_SystemStatus_01 0 "Not Static" 1 "Staic Balance" 2 "Discharge false Balance" ;
VAL_ 2417487425 S2P_Bal_Strategy_01 0 "Active Balance" 1 "Passive Static" ;
VAL_ 2417487425 S2P_Bal_ForceBalMode_01 1 "Base on time " 2 "Base on Target Vol" 3 "Base on Ave Vol" ;
VAL_ 2417487425 S2P_Bal_CellTempFault_01 0 "Nomal" 1 "Fault" ;
VAL_ 2417487425 S2P_Bal_CellVoltFail_01 0 "Nomal" 1 "Fault" ;
VAL_ 2417487425 S2P_Bal_CloseBalInstruct_01 0 "Nomal" 1 "Fault" ;
VAL_ 2417487425 S2P_Bal_CCanTimeOut_01 0 "Nomal" 1 "Fault" ;
VAL_ 2417487425 S2P_Bal_CellOffLine_01 0 "Nomal" 1 "Fault" ;
VAL_ 2417487425 S2P_Bal_BalanceCircuitFault_01 0 "Nomal" 1 "Fault" ;
VAL_ 2417487425 S2P_Bal_CSCSourceVoltFault_01 0 "Nomal" 1 "Fault" ;
VAL_ 2417487425 S2P_Bal_CellVoltOverFault_01 0 "Nomal" 1 "Fault" ;
VAL_ 2417487425 S2P_Bal_CellVoltLowFault_01 0 "Nomal" 1 "Fault" ;
VAL_ 2417487425 S2P_Bal_CSCPCBTempFault_01 0 "Nomal" 1 "Fault" ;
VAL_ 2417487425 S2P_Bal_CSCSourceCurrLowFault_01 0 "Nomal" 1 "Fault" ;
VAL_ 2417487425 S2P_Bal_CSCSourceCurrOvrFault_01 0 "Nomal" 1 "Fault" ;
VAL_ 2417487426 S2P_Bal_CSCNum_02 0 "No CSC" 1 "CSC 1" 2 "CSC 2" 3 "CSC 3" 4 "CSC 4" 5 "CSC 5" 6 "CSC 6" 7 "CSC 7" 8 "CSC 8" 9 "CSC 9" 10 "CSC 10" 11 "CSC 11" 12 "CSC 12" 13 "CSC 13" 14 "CSC 14" 15 "CSC 15" 16 "CSC 16" 17 "CSC 17" 18 "CSC 18" 19 "CSC 19" 20 "CSC 20" 21 "CSC 21" 22 "CSC 22" 23 "CSC 23" 24 "CSC 24" 25 "CSC 25" 26 "CSC 26" 27 "CSC 27" 28 "CSC 28" 29 "CSC 29" 30 "CSC 30" 31 "CSC 31" ;
VAL_ 2417487426 S2P_Bal_CellNum_02 1 "Cell 1" 2 "Cell 2" 3 "Cell 3" 4 "Cell 4" 5 "Cell 5" 6 "Cell 6" 7 "Cell 7" 8 "Cell 8" 9 "Cell 9" 10 "Cell 10" 11 "Cell 11" 12 "Cell 12" 13 "Cell 13" 14 "Cell 14" 15 "Cell 15" 16 "Cell 16" 63 "Null" ;
VAL_ 2417487426 S2P_Bal_Type_02 0 "Balance stop" 1 "charge Balance" 2 "discharge Balance" ;
VAL_ 2417487426 S2P_Bal_TypeLevel_02 0 "Not Balance" 1 "Low end Balance" 2 "High end Balance" 3 "Force Balance" ;
VAL_ 2417487426 S2P_Bal_SystemStatus_02 0 "Not Static" 1 "Staic Balance" 2 "Discharge false Balance" ;
VAL_ 2417487426 S2P_Bal_Strategy_02 0 "Active Balance" 1 "Passive Static" ;
VAL_ 2417487426 S2P_Bal_ForceBalMode_02 1 "Base on time " 2 "Base on Target Vol" 3 "Base on Ave Vol" ;
VAL_ 2417487426 S2P_Bal_CellTempFault_02 0 "Nomal" 1 "Fault" ;
VAL_ 2417487426 S2P_Bal_CellVoltFail_02 0 "Nomal" 1 "Fault" ;
VAL_ 2417487426 S2P_Bal_CloseBalInstruct_02 0 "Nomal" 1 "Fault" ;
VAL_ 2417487426 S2P_Bal_CCanTimeOut_02 0 "Nomal" 1 "Fault" ;
VAL_ 2417487426 S2P_Bal_CellOffLine_02 0 "Nomal" 1 "Fault" ;
VAL_ 2417487426 S2P_Bal_BalanceCircuitFault_02 0 "Nomal" 1 "Fault" ;
VAL_ 2417487426 S2P_Bal_CSCSourceVoltFault_02 0 "Nomal" 1 "Fault" ;
VAL_ 2417487426 S2P_Bal_CellVoltOverFault_02 0 "Nomal" 1 "Fault" ;
VAL_ 2417487426 S2P_Bal_CellVoltLowFault_02 0 "Nomal" 1 "Fault" ;
VAL_ 2417487426 S2P_Bal_CSCPCBTempFault_02 0 "Nomal" 1 "Fault" ;
VAL_ 2417487426 S2P_Bal_CSCSourceCurrLowFault_02 0 "Nomal" 1 "Fault" ;
VAL_ 2417487426 S2P_Bal_CSCSourceCurrOvrFault_02 0 "Nomal" 1 "Fault" ;
VAL_ 2417487427 S2P_Bal_CSCNum_03 0 "No CSC" 1 "CSC 1" 2 "CSC 2" 3 "CSC 3" 4 "CSC 4" 5 "CSC 5" 6 "CSC 6" 7 "CSC 7" 8 "CSC 8" 9 "CSC 9" 10 "CSC 10" 11 "CSC 11" 12 "CSC 12" 13 "CSC 13" 14 "CSC 14" 15 "CSC 15" 16 "CSC 16" 17 "CSC 17" 18 "CSC 18" 19 "CSC 19" 20 "CSC 20" 21 "CSC 21" 22 "CSC 22" 23 "CSC 23" 24 "CSC 24" 25 "CSC 25" 26 "CSC 26" 27 "CSC 27" 28 "CSC 28" 29 "CSC 29" 30 "CSC 30" 31 "CSC 31" ;
VAL_ 2417487427 S2P_Bal_CellNum_03 1 "Cell 1" 2 "Cell 2" 3 "Cell 3" 4 "Cell 4" 5 "Cell 5" 6 "Cell 6" 7 "Cell 7" 8 "Cell 8" 9 "Cell 9" 10 "Cell 10" 11 "Cell 11" 12 "Cell 12" 13 "Cell 13" 14 "Cell 14" 15 "Cell 15" 16 "Cell 16" 63 "Null" ;
VAL_ 2417487427 S2P_Bal_Type_03 0 "Balance stop" 1 "charge Balance" 2 "discharge Balance" ;
VAL_ 2417487427 S2P_Bal_TypeLevel_03 0 "Not Balance" 1 "Low end Balance" 2 "High end Balance" 3 "Force Balance" ;
VAL_ 2417487427 S2P_Bal_SystemStatus_03 0 "Not Static" 1 "Staic Balance" 2 "Discharge false Balance" ;
VAL_ 2417487427 S2P_Bal_Strategy_03 0 "Active Balance" 1 "Passive Static" ;
VAL_ 2417487427 S2P_Bal_ForceBalMode_03 1 "Base on time " 2 "Base on Target Vol" 3 "Base on Ave Vol" ;
VAL_ 2417487427 S2P_Bal_CellTempFault_03 0 "Nomal" 1 "Fault" ;
VAL_ 2417487427 S2P_Bal_CellVoltFail_03 0 "Nomal" 1 "Fault" ;
VAL_ 2417487427 S2P_Bal_CloseBalInstruct_03 0 "Nomal" 1 "Fault" ;
VAL_ 2417487427 S2P_Bal_CCanTimeOut_03 0 "Nomal" 1 "Fault" ;
VAL_ 2417487427 S2P_Bal_CellOffLine_03 0 "Nomal" 1 "Fault" ;
VAL_ 2417487427 S2P_Bal_BalanceCircuitFault_03 0 "Nomal" 1 "Fault" ;
VAL_ 2417487427 S2P_Bal_CSCSourceVoltFault_03 0 "Nomal" 1 "Fault" ;
VAL_ 2417487427 S2P_Bal_CellVoltOverFault_03 0 "Nomal" 1 "Fault" ;
VAL_ 2417487427 S2P_Bal_CellVoltLowFault_03 0 "Nomal" 1 "Fault" ;
VAL_ 2417487427 S2P_Bal_CSCPCBTempFault_03 0 "Nomal" 1 "Fault" ;
VAL_ 2417487427 S2P_Bal_CSCSourceCurrLowFault_03 0 "Nomal" 1 "Fault" ;
VAL_ 2417487427 S2P_Bal_CSCSourceCurrOvrFault_03 0 "Nomal" 1 "Fault" ;
VAL_ 2417487428 S2P_Bal_CSCNum_04 0 "No CSC" 1 "CSC 1" 2 "CSC 2" 3 "CSC 3" 4 "CSC 4" 5 "CSC 5" 6 "CSC 6" 7 "CSC 7" 8 "CSC 8" 9 "CSC 9" 10 "CSC 10" 11 "CSC 11" 12 "CSC 12" 13 "CSC 13" 14 "CSC 14" 15 "CSC 15" 16 "CSC 16" 17 "CSC 17" 18 "CSC 18" 19 "CSC 19" 20 "CSC 20" 21 "CSC 21" 22 "CSC 22" 23 "CSC 23" 24 "CSC 24" 25 "CSC 25" 26 "CSC 26" 27 "CSC 27" 28 "CSC 28" 29 "CSC 29" 30 "CSC 30" 31 "CSC 31" ;
VAL_ 2417487428 S2P_Bal_CellNum_04 1 "Cell 1" 2 "Cell 2" 3 "Cell 3" 4 "Cell 4" 5 "Cell 5" 6 "Cell 6" 7 "Cell 7" 8 "Cell 8" 9 "Cell 9" 10 "Cell 10" 11 "Cell 11" 12 "Cell 12" 13 "Cell 13" 14 "Cell 14" 15 "Cell 15" 16 "Cell 16" 63 "Null" ;
VAL_ 2417487428 S2P_Bal_Type_04 0 "Balance stop" 1 "charge Balance" 2 "discharge Balance" ;
VAL_ 2417487428 S2P_Bal_TypeLevel_04 0 "Not Balance" 1 "Low end Balance" 2 "High end Balance" 3 "Force Balance" ;
VAL_ 2417487428 S2P_Bal_SystemStatus_04 0 "Not Static" 1 "Staic Balance" 2 "Discharge false Balance" ;
VAL_ 2417487428 S2P_Bal_Strategy_04 0 "Active Balance" 1 "Passive Static" ;
VAL_ 2417487428 S2P_Bal_ForceBalMode_04 1 "Base on time " 2 "Base on Target Vol" 3 "Base on Ave Vol" ;
VAL_ 2417487428 S2P_Bal_CellTempFault_04 0 "Nomal" 1 "Fault" ;
VAL_ 2417487428 S2P_Bal_CellVoltFail_04 0 "Nomal" 1 "Fault" ;
VAL_ 2417487428 S2P_Bal_CloseBalInstruct_04 0 "Nomal" 1 "Fault" ;
VAL_ 2417487428 S2P_Bal_CCanTimeOut_04 0 "Nomal" 1 "Fault" ;
VAL_ 2417487428 S2P_Bal_CellOffLine_04 0 "Nomal" 1 "Fault" ;
VAL_ 2417487428 S2P_Bal_BalanceCircuitFault_04 0 "Nomal" 1 "Fault" ;
VAL_ 2417487428 S2P_Bal_CSCSourceVoltFault_04 0 "Nomal" 1 "Fault" ;
VAL_ 2417487428 S2P_Bal_CellVoltOverFault_04 0 "Nomal" 1 "Fault" ;
VAL_ 2417487428 S2P_Bal_CellVoltLowFault_04 0 "Nomal" 1 "Fault" ;
VAL_ 2417487428 S2P_Bal_CSCPCBTempFault_04 0 "Nomal" 1 "Fault" ;
VAL_ 2417487428 S2P_Bal_CSCSourceCurrLowFault_04 0 "Nomal" 1 "Fault" ;
VAL_ 2417487428 S2P_Bal_CSCSourceCurrOvrFault_04 0 "Nomal" 1 "Fault" ;
VAL_ 2417487429 S2P_Bal_CSCNum_05 0 "No CSC" 1 "CSC 1" 2 "CSC 2" 3 "CSC 3" 4 "CSC 4" 5 "CSC 5" 6 "CSC 6" 7 "CSC 7" 8 "CSC 8" 9 "CSC 9" 10 "CSC 10" 11 "CSC 11" 12 "CSC 12" 13 "CSC 13" 14 "CSC 14" 15 "CSC 15" 16 "CSC 16" 17 "CSC 17" 18 "CSC 18" 19 "CSC 19" 20 "CSC 20" 21 "CSC 21" 22 "CSC 22" 23 "CSC 23" 24 "CSC 24" 25 "CSC 25" 26 "CSC 26" 27 "CSC 27" 28 "CSC 28" 29 "CSC 29" 30 "CSC 30" 31 "CSC 31" ;
VAL_ 2417487429 S2P_Bal_CellNum_05 1 "Cell 1" 2 "Cell 2" 3 "Cell 3" 4 "Cell 4" 5 "Cell 5" 6 "Cell 6" 7 "Cell 7" 8 "Cell 8" 9 "Cell 9" 10 "Cell 10" 11 "Cell 11" 12 "Cell 12" 13 "Cell 13" 14 "Cell 14" 15 "Cell 15" 16 "Cell 16" 63 "Null" ;
VAL_ 2417487429 S2P_Bal_Type_05 0 "Balance stop" 1 "charge Balance" 2 "discharge Balance" ;
VAL_ 2417487429 S2P_Bal_TypeLevel_05 0 "Not Balance" 1 "Low end Balance" 2 "High end Balance" 3 "Force Balance" ;
VAL_ 2417487429 S2P_Bal_SystemStatus_05 0 "Not Static" 1 "Staic Balance" 2 "Discharge false Balance" ;
VAL_ 2417487429 S2P_Bal_Strategy_05 0 "Active Balance" 1 "Passive Static" ;
VAL_ 2417487429 S2P_Bal_ForceBalMode_05 1 "Base on time " 2 "Base on Target Vol" 3 "Base on Ave Vol" ;
VAL_ 2417487429 S2P_Bal_CellTempFault_05 0 "Nomal" 1 "Fault" ;
VAL_ 2417487429 S2P_Bal_CellVoltFail_05 0 "Nomal" 1 "Fault" ;
VAL_ 2417487429 S2P_Bal_CloseBalInstruct_05 0 "Nomal" 1 "Fault" ;
VAL_ 2417487429 S2P_Bal_CCanTimeOut_05 0 "Nomal" 1 "Fault" ;
VAL_ 2417487429 S2P_Bal_CellOffLine_05 0 "Nomal" 1 "Fault" ;
VAL_ 2417487429 S2P_Bal_BalanceCircuitFault_05 0 "Nomal" 1 "Fault" ;
VAL_ 2417487429 S2P_Bal_CSCSourceVoltFault_05 0 "Nomal" 1 "Fault" ;
VAL_ 2417487429 S2P_Bal_CellVoltOverFault_05 0 "Nomal" 1 "Fault" ;
VAL_ 2417487429 S2P_Bal_CellVoltLowFault_05 0 "Nomal" 1 "Fault" ;
VAL_ 2417487429 S2P_Bal_CSCPCBTempFault_05 0 "Nomal" 1 "Fault" ;
VAL_ 2417487429 S2P_Bal_CSCSourceCurrLowFault_05 0 "Nomal" 1 "Fault" ;
VAL_ 2417487429 S2P_Bal_CSCSourceCurrOvrFault_05 0 "Nomal" 1 "Fault" ;
VAL_ 2417487430 S2P_Bal_CSCNum_06 0 "No CSC" 1 "CSC 1" 2 "CSC 2" 3 "CSC 3" 4 "CSC 4" 5 "CSC 5" 6 "CSC 6" 7 "CSC 7" 8 "CSC 8" 9 "CSC 9" 10 "CSC 10" 11 "CSC 11" 12 "CSC 12" 13 "CSC 13" 14 "CSC 14" 15 "CSC 15" 16 "CSC 16" 17 "CSC 17" 18 "CSC 18" 19 "CSC 19" 20 "CSC 20" 21 "CSC 21" 22 "CSC 22" 23 "CSC 23" 24 "CSC 24" 25 "CSC 25" 26 "CSC 26" 27 "CSC 27" 28 "CSC 28" 29 "CSC 29" 30 "CSC 30" 31 "CSC 31" ;
VAL_ 2417487430 S2P_Bal_CellNum_06 1 "Cell 1" 2 "Cell 2" 3 "Cell 3" 4 "Cell 4" 5 "Cell 5" 6 "Cell 6" 7 "Cell 7" 8 "Cell 8" 9 "Cell 9" 10 "Cell 10" 11 "Cell 11" 12 "Cell 12" 13 "Cell 13" 14 "Cell 14" 15 "Cell 15" 16 "Cell 16" 63 "Null" ;
VAL_ 2417487430 S2P_Bal_Type_06 0 "Balance stop" 1 "charge Balance" 2 "discharge Balance" ;
VAL_ 2417487430 S2P_Bal_TypeLevel_06 0 "Not Balance" 1 "Low end Balance" 2 "High end Balance" 3 "Force Balance" ;
VAL_ 2417487430 S2P_Bal_SystemStatus_06 0 "Not Static" 1 "Staic Balance" 2 "Discharge false Balance" ;
VAL_ 2417487430 S2P_Bal_Strategy_06 0 "Active Balance" 1 "Passive Static" ;
VAL_ 2417487430 S2P_Bal_ForceBalMode_06 1 "Base on time " 2 "Base on Target Vol" 3 "Base on Ave Vol" ;
VAL_ 2417487430 S2P_Bal_CellTempFault_06 0 "Nomal" 1 "Fault" ;
VAL_ 2417487430 S2P_Bal_CellVoltFail_06 0 "Nomal" 1 "Fault" ;
VAL_ 2417487430 S2P_Bal_CloseBalInstruct_06 0 "Nomal" 1 "Fault" ;
VAL_ 2417487430 S2P_Bal_CCanTimeOut_06 0 "Nomal" 1 "Fault" ;
VAL_ 2417487430 S2P_Bal_CellOffLine_06 0 "Nomal" 1 "Fault" ;
VAL_ 2417487430 S2P_Bal_BalanceCircuitFault_06 0 "Nomal" 1 "Fault" ;
VAL_ 2417487430 S2P_Bal_CSCSourceVoltFault_06 0 "Nomal" 1 "Fault" ;
VAL_ 2417487430 S2P_Bal_CellVoltOverFault_06 0 "Nomal" 1 "Fault" ;
VAL_ 2417487430 S2P_Bal_CellVoltLowFault_06 0 "Nomal" 1 "Fault" ;
VAL_ 2417487430 S2P_Bal_CSCPCBTempFault_06 0 "Nomal" 1 "Fault" ;
VAL_ 2417487430 S2P_Bal_CSCSourceCurrLowFault_06 0 "Nomal" 1 "Fault" ;
VAL_ 2417487430 S2P_Bal_CSCSourceCurrOvrFault_06 0 "Nomal" 1 "Fault" ;
VAL_ 2417487431 S2P_Bal_CSCNum_07 0 "No CSC" 1 "CSC 1" 2 "CSC 2" 3 "CSC 3" 4 "CSC 4" 5 "CSC 5" 6 "CSC 6" 7 "CSC 7" 8 "CSC 8" 9 "CSC 9" 10 "CSC 10" 11 "CSC 11" 12 "CSC 12" 13 "CSC 13" 14 "CSC 14" 15 "CSC 15" 16 "CSC 16" 17 "CSC 17" 18 "CSC 18" 19 "CSC 19" 20 "CSC 20" 21 "CSC 21" 22 "CSC 22" 23 "CSC 23" 24 "CSC 24" 25 "CSC 25" 26 "CSC 26" 27 "CSC 27" 28 "CSC 28" 29 "CSC 29" 30 "CSC 30" 31 "CSC 31" ;
VAL_ 2417487431 S2P_Bal_CellNum_07 1 "Cell 1" 2 "Cell 2" 3 "Cell 3" 4 "Cell 4" 5 "Cell 5" 6 "Cell 6" 7 "Cell 7" 8 "Cell 8" 9 "Cell 9" 10 "Cell 10" 11 "Cell 11" 12 "Cell 12" 13 "Cell 13" 14 "Cell 14" 15 "Cell 15" 16 "Cell 16" 63 "Null" ;
VAL_ 2417487431 S2P_Bal_Type_07 0 "Balance stop" 1 "charge Balance" 2 "discharge Balance" ;
VAL_ 2417487431 S2P_Bal_TypeLevel_07 0 "Not Balance" 1 "Low end Balance" 2 "High end Balance" 3 "Force Balance" ;
VAL_ 2417487431 S2P_Bal_SystemStatus_07 0 "Not Static" 1 "Staic Balance" 2 "Discharge false Balance" ;
VAL_ 2417487431 S2P_Bal_Strategy_07 0 "Active Balance" 1 "Passive Static" ;
VAL_ 2417487431 S2P_Bal_ForceBalMode_07 1 "Base on time " 2 "Base on Target Vol" 3 "Base on Ave Vol" ;
VAL_ 2417487431 S2P_Bal_CellTempFault_07 0 "Nomal" 1 "Fault" ;
VAL_ 2417487431 S2P_Bal_CellVoltFail_07 0 "Nomal" 1 "Fault" ;
VAL_ 2417487431 S2P_Bal_CloseBalInstruct_07 0 "Nomal" 1 "Fault" ;
VAL_ 2417487431 S2P_Bal_CCanTimeOut_07 0 "Nomal" 1 "Fault" ;
VAL_ 2417487431 S2P_Bal_CellOffLine_07 0 "Nomal" 1 "Fault" ;
VAL_ 2417487431 S2P_Bal_BalanceCircuitFault_07 0 "Nomal" 1 "Fault" ;
VAL_ 2417487431 S2P_Bal_CSCSourceVoltFault_07 0 "Nomal" 1 "Fault" ;
VAL_ 2417487431 S2P_Bal_CellVoltOverFault_07 0 "Nomal" 1 "Fault" ;
VAL_ 2417487431 S2P_Bal_CellVoltLowFault_07 0 "Nomal" 1 "Fault" ;
VAL_ 2417487431 S2P_Bal_CSCPCBTempFault_07 0 "Nomal" 1 "Fault" ;
VAL_ 2417487431 S2P_Bal_CSCSourceCurrLowFault_07 0 "Nomal" 1 "Fault" ;
VAL_ 2417487431 S2P_Bal_CSCSourceCurrOvrFault_07 0 "Nomal" 1 "Fault" ;
VAL_ 2417487432 S2P_Bal_CSCNum_08 0 "No CSC" 1 "CSC 1" 2 "CSC 2" 3 "CSC 3" 4 "CSC 4" 5 "CSC 5" 6 "CSC 6" 7 "CSC 7" 8 "CSC 8" 9 "CSC 9" 10 "CSC 10" 11 "CSC 11" 12 "CSC 12" 13 "CSC 13" 14 "CSC 14" 15 "CSC 15" 16 "CSC 16" 17 "CSC 17" 18 "CSC 18" 19 "CSC 19" 20 "CSC 20" 21 "CSC 21" 22 "CSC 22" 23 "CSC 23" 24 "CSC 24" 25 "CSC 25" 26 "CSC 26" 27 "CSC 27" 28 "CSC 28" 29 "CSC 29" 30 "CSC 30" 31 "CSC 31" ;
VAL_ 2417487432 S2P_Bal_CellNum_08 1 "Cell 1" 2 "Cell 2" 3 "Cell 3" 4 "Cell 4" 5 "Cell 5" 6 "Cell 6" 7 "Cell 7" 8 "Cell 8" 9 "Cell 9" 10 "Cell 10" 11 "Cell 11" 12 "Cell 12" 13 "Cell 13" 14 "Cell 14" 15 "Cell 15" 16 "Cell 16" 63 "Null" ;
VAL_ 2417487432 S2P_Bal_Type_08 0 "Balance stop" 1 "charge Balance" 2 "discharge Balance" ;
VAL_ 2417487432 S2P_Bal_TypeLevel_08 0 "Not Balance" 1 "Low end Balance" 2 "High end Balance" 3 "Force Balance" ;
VAL_ 2417487432 S2P_Bal_SystemStatus_08 0 "Not Static" 1 "Staic Balance" 2 "Discharge false Balance" ;
VAL_ 2417487432 S2P_Bal_Strategy_08 0 "Active Balance" 1 "Passive Static" ;
VAL_ 2417487432 S2P_Bal_ForceBalMode_08 1 "Base on time " 2 "Base on Target Vol" 3 "Base on Ave Vol" ;
VAL_ 2417487432 S2P_Bal_CellTempFault_08 0 "Nomal" 1 "Fault" ;
VAL_ 2417487432 S2P_Bal_CellVoltFail_08 0 "Nomal" 1 "Fault" ;
VAL_ 2417487432 S2P_Bal_CloseBalInstruct_08 0 "Nomal" 1 "Fault" ;
VAL_ 2417487432 S2P_Bal_CCanTimeOut_08 0 "Nomal" 1 "Fault" ;
VAL_ 2417487432 S2P_Bal_CellOffLine_08 0 "Nomal" 1 "Fault" ;
VAL_ 2417487432 S2P_Bal_BalanceCircuitFault_08 0 "Nomal" 1 "Fault" ;
VAL_ 2417487432 S2P_Bal_CSCSourceVoltFault_08 0 "Nomal" 1 "Fault" ;
VAL_ 2417487432 S2P_Bal_CellVoltOverFault_08 0 "Nomal" 1 "Fault" ;
VAL_ 2417487432 S2P_Bal_CellVoltLowFault_08 0 "Nomal" 1 "Fault" ;
VAL_ 2417487432 S2P_Bal_CSCPCBTempFault_08 0 "Nomal" 1 "Fault" ;
VAL_ 2417487432 S2P_Bal_CSCSourceCurrLowFault_08 0 "Nomal" 1 "Fault" ;
VAL_ 2417487432 S2P_Bal_CSCSourceCurrOvrFault_08 0 "Nomal" 1 "Fault" ;
VAL_ 2417487433 S2P_Bal_CSCNum_09 0 "No CSC" 1 "CSC 1" 2 "CSC 2" 3 "CSC 3" 4 "CSC 4" 5 "CSC 5" 6 "CSC 6" 7 "CSC 7" 8 "CSC 8" 9 "CSC 9" 10 "CSC 10" 11 "CSC 11" 12 "CSC 12" 13 "CSC 13" 14 "CSC 14" 15 "CSC 15" 16 "CSC 16" 17 "CSC 17" 18 "CSC 18" 19 "CSC 19" 20 "CSC 20" 21 "CSC 21" 22 "CSC 22" 23 "CSC 23" 24 "CSC 24" 25 "CSC 25" 26 "CSC 26" 27 "CSC 27" 28 "CSC 28" 29 "CSC 29" 30 "CSC 30" 31 "CSC 31" ;
VAL_ 2417487433 S2P_Bal_CellNum_09 1 "Cell 1" 2 "Cell 2" 3 "Cell 3" 4 "Cell 4" 5 "Cell 5" 6 "Cell 6" 7 "Cell 7" 8 "Cell 8" 9 "Cell 9" 10 "Cell 10" 11 "Cell 11" 12 "Cell 12" 13 "Cell 13" 14 "Cell 14" 15 "Cell 15" 16 "Cell 16" 63 "Null" ;
VAL_ 2417487433 S2P_Bal_Type_09 0 "Balance stop" 1 "charge Balance" 2 "discharge Balance" ;
VAL_ 2417487433 S2P_Bal_TypeLevel_09 0 "Not Balance" 1 "Low end Balance" 2 "High end Balance" 3 "Force Balance" ;
VAL_ 2417487433 S2P_Bal_SystemStatus_09 0 "Not Static" 1 "Staic Balance" 2 "Discharge false Balance" ;
VAL_ 2417487433 S2P_Bal_Strategy_09 0 "Active Balance" 1 "Passive Static" ;
VAL_ 2417487433 S2P_Bal_ForceBalMode_09 1 "Base on time " 2 "Base on Target Vol" 3 "Base on Ave Vol" ;
VAL_ 2417487433 S2P_Bal_CellTempFault_09 0 "Nomal" 1 "Fault" ;
VAL_ 2417487433 S2P_Bal_CellVoltFail_09 0 "Nomal" 1 "Fault" ;
VAL_ 2417487433 S2P_Bal_CloseBalInstruct_09 0 "Nomal" 1 "Fault" ;
VAL_ 2417487433 S2P_Bal_CCanTimeOut_09 0 "Nomal" 1 "Fault" ;
VAL_ 2417487433 S2P_Bal_CellOffLine_09 0 "Nomal" 1 "Fault" ;
VAL_ 2417487433 S2P_Bal_BalanceCircuitFault_09 0 "Nomal" 1 "Fault" ;
VAL_ 2417487433 S2P_Bal_CSCSourceVoltFault_09 0 "Nomal" 1 "Fault" ;
VAL_ 2417487433 S2P_Bal_CellVoltOverFault_09 0 "Nomal" 1 "Fault" ;
VAL_ 2417487433 S2P_Bal_CellVoltLowFault_09 0 "Nomal" 1 "Fault" ;
VAL_ 2417487433 S2P_Bal_CSCPCBTempFault_09 0 "Nomal" 1 "Fault" ;
VAL_ 2417487433 S2P_Bal_CSCSourceCurrLowFault_09 0 "Nomal" 1 "Fault" ;
VAL_ 2417487433 S2P_Bal_CSCSourceCurrOvrFault_09 0 "Nomal" 1 "Fault" ;
VAL_ 2417487434 S2P_Bal_CSCNum_10 0 "No CSC" 1 "CSC 1" 2 "CSC 2" 3 "CSC 3" 4 "CSC 4" 5 "CSC 5" 6 "CSC 6" 7 "CSC 7" 8 "CSC 8" 9 "CSC 9" 10 "CSC 10" 11 "CSC 11" 12 "CSC 12" 13 "CSC 13" 14 "CSC 14" 15 "CSC 15" 16 "CSC 16" 17 "CSC 17" 18 "CSC 18" 19 "CSC 19" 20 "CSC 20" 21 "CSC 21" 22 "CSC 22" 23 "CSC 23" 24 "CSC 24" 25 "CSC 25" 26 "CSC 26" 27 "CSC 27" 28 "CSC 28" 29 "CSC 29" 30 "CSC 30" 31 "CSC 31" ;
VAL_ 2417487434 S2P_Bal_CellNum_10 1 "Cell 1" 2 "Cell 2" 3 "Cell 3" 4 "Cell 4" 5 "Cell 5" 6 "Cell 6" 7 "Cell 7" 8 "Cell 8" 9 "Cell 9" 10 "Cell 10" 11 "Cell 11" 12 "Cell 12" 13 "Cell 13" 14 "Cell 14" 15 "Cell 15" 16 "Cell 16" 63 "Null" ;
VAL_ 2417487434 S2P_Bal_Type_10 0 "Balance stop" 1 "charge Balance" 2 "discharge Balance" ;
VAL_ 2417487434 S2P_Bal_TypeLevel_10 0 "Not Balance" 1 "Low end Balance" 2 "High end Balance" 3 "Force Balance" ;
VAL_ 2417487434 S2P_Bal_SystemStatus_10 0 "Not Static" 1 "Staic Balance" 2 "Discharge false Balance" ;
VAL_ 2417487434 S2P_Bal_Strategy_10 0 "Active Balance" 1 "Passive Static" ;
VAL_ 2417487434 S2P_Bal_ForceBalMode_10 1 "Base on time " 2 "Base on Target Vol" 3 "Base on Ave Vol" ;
VAL_ 2417487434 S2P_Bal_CellTempFault_10 0 "Nomal" 1 "Fault" ;
VAL_ 2417487434 S2P_Bal_CellVoltFail_10 0 "Nomal" 1 "Fault" ;
VAL_ 2417487434 S2P_Bal_CloseBalInstruct_10 0 "Nomal" 1 "Fault" ;
VAL_ 2417487434 S2P_Bal_CCanTimeOut_10 0 "Nomal" 1 "Fault" ;
VAL_ 2417487434 S2P_Bal_CellOffLine_10 0 "Nomal" 1 "Fault" ;
VAL_ 2417487434 S2P_Bal_BalanceCircuitFault_10 0 "Nomal" 1 "Fault" ;
VAL_ 2417487434 S2P_Bal_CSCSourceVoltFault_10 0 "Nomal" 1 "Fault" ;
VAL_ 2417487434 S2P_Bal_CellVoltOverFault_10 0 "Nomal" 1 "Fault" ;
VAL_ 2417487434 S2P_Bal_CellVoltLowFault_10 0 "Nomal" 1 "Fault" ;
VAL_ 2417487434 S2P_Bal_CSCPCBTempFault_10 0 "Nomal" 1 "Fault" ;
VAL_ 2417487434 S2P_Bal_CSCSourceCurrLowFault_10 0 "Nomal" 1 "Fault" ;
VAL_ 2417487434 S2P_Bal_CSCSourceCurrOvrFault_10 0 "Nomal" 1 "Fault" ;
VAL_ 2417487435 S2P_Bal_CSCNum_11 0 "No CSC" 1 "CSC 1" 2 "CSC 2" 3 "CSC 3" 4 "CSC 4" 5 "CSC 5" 6 "CSC 6" 7 "CSC 7" 8 "CSC 8" 9 "CSC 9" 10 "CSC 10" 11 "CSC 11" 12 "CSC 12" 13 "CSC 13" 14 "CSC 14" 15 "CSC 15" 16 "CSC 16" 17 "CSC 17" 18 "CSC 18" 19 "CSC 19" 20 "CSC 20" 21 "CSC 21" 22 "CSC 22" 23 "CSC 23" 24 "CSC 24" 25 "CSC 25" 26 "CSC 26" 27 "CSC 27" 28 "CSC 28" 29 "CSC 29" 30 "CSC 30" 31 "CSC 31" ;
VAL_ 2417487435 S2P_Bal_CellNum_11 1 "Cell 1" 2 "Cell 2" 3 "Cell 3" 4 "Cell 4" 5 "Cell 5" 6 "Cell 6" 7 "Cell 7" 8 "Cell 8" 9 "Cell 9" 10 "Cell 10" 11 "Cell 11" 12 "Cell 12" 13 "Cell 13" 14 "Cell 14" 15 "Cell 15" 16 "Cell 16" 63 "Null" ;
VAL_ 2417487435 S2P_Bal_Type_11 0 "Balance stop" 1 "charge Balance" 2 "discharge Balance" ;
VAL_ 2417487435 S2P_Bal_TypeLevel_11 0 "Not Balance" 1 "Low end Balance" 2 "High end Balance" 3 "Force Balance" ;
VAL_ 2417487435 S2P_Bal_SystemStatus_11 0 "Not Static" 1 "Staic Balance" 2 "Discharge false Balance" ;
VAL_ 2417487435 S2P_Bal_Strategy_11 0 "Active Balance" 1 "Passive Static" ;
VAL_ 2417487435 S2P_Bal_ForceBalMode_11 1 "Base on time " 2 "Base on Target Vol" 3 "Base on Ave Vol" ;
VAL_ 2417487435 S2P_Bal_CellTempFault_11 0 "Nomal" 1 "Fault" ;
VAL_ 2417487435 S2P_Bal_CellVoltFail_11 0 "Nomal" 1 "Fault" ;
VAL_ 2417487435 S2P_Bal_CloseBalInstruct_11 0 "Nomal" 1 "Fault" ;
VAL_ 2417487435 S2P_Bal_CCanTimeOut_11 0 "Nomal" 1 "Fault" ;
VAL_ 2417487435 S2P_Bal_CellOffLine_11 0 "Nomal" 1 "Fault" ;
VAL_ 2417487435 S2P_Bal_BalanceCircuitFault_11 0 "Nomal" 1 "Fault" ;
VAL_ 2417487435 S2P_Bal_CSCSourceVoltFault_11 0 "Nomal" 1 "Fault" ;
VAL_ 2417487435 S2P_Bal_CellVoltOverFault_11 0 "Nomal" 1 "Fault" ;
VAL_ 2417487435 S2P_Bal_CellVoltLowFault_11 0 "Nomal" 1 "Fault" ;
VAL_ 2417487435 S2P_Bal_CSCPCBTempFault_11 0 "Nomal" 1 "Fault" ;
VAL_ 2417487435 S2P_Bal_CSCSourceCurrLowFault_11 0 "Nomal" 1 "Fault" ;
VAL_ 2417487435 S2P_Bal_CSCSourceCurrOvrFault_11 0 "Nomal" 1 "Fault" ;
VAL_ 2417487436 S2P_Bal_CSCNum_12 0 "No CSC" 1 "CSC 1" 2 "CSC 2" 3 "CSC 3" 4 "CSC 4" 5 "CSC 5" 6 "CSC 6" 7 "CSC 7" 8 "CSC 8" 9 "CSC 9" 10 "CSC 10" 11 "CSC 11" 12 "CSC 12" 13 "CSC 13" 14 "CSC 14" 15 "CSC 15" 16 "CSC 16" 17 "CSC 17" 18 "CSC 18" 19 "CSC 19" 20 "CSC 20" 21 "CSC 21" 22 "CSC 22" 23 "CSC 23" 24 "CSC 24" 25 "CSC 25" 26 "CSC 26" 27 "CSC 27" 28 "CSC 28" 29 "CSC 29" 30 "CSC 30" 31 "CSC 31" ;
VAL_ 2417487436 S2P_Bal_CellNum_12 1 "Cell 1" 2 "Cell 2" 3 "Cell 3" 4 "Cell 4" 5 "Cell 5" 6 "Cell 6" 7 "Cell 7" 8 "Cell 8" 9 "Cell 9" 10 "Cell 10" 11 "Cell 11" 12 "Cell 12" 13 "Cell 13" 14 "Cell 14" 15 "Cell 15" 16 "Cell 16" 63 "Null" ;
VAL_ 2417487436 S2P_Bal_Type_12 0 "Balance stop" 1 "charge Balance" 2 "discharge Balance" ;
VAL_ 2417487436 S2P_Bal_TypeLevel_12 0 "Not Balance" 1 "Low end Balance" 2 "High end Balance" 3 "Force Balance" ;
VAL_ 2417487436 S2P_Bal_SystemStatus_12 0 "Not Static" 1 "Staic Balance" 2 "Discharge false Balance" ;
VAL_ 2417487436 S2P_Bal_Strategy_12 0 "Active Balance" 1 "Passive Static" ;
VAL_ 2417487436 S2P_Bal_ForceBalMode_12 1 "Base on time " 2 "Base on Target Vol" 3 "Base on Ave Vol" ;
VAL_ 2417487436 S2P_Bal_CellTempFault_12 0 "Nomal" 1 "Fault" ;
VAL_ 2417487436 S2P_Bal_CellVoltFail_12 0 "Nomal" 1 "Fault" ;
VAL_ 2417487436 S2P_Bal_CloseBalInstruct_12 0 "Nomal" 1 "Fault" ;
VAL_ 2417487436 S2P_Bal_CCanTimeOut_12 0 "Nomal" 1 "Fault" ;
VAL_ 2417487436 S2P_Bal_CellOffLine_12 0 "Nomal" 1 "Fault" ;
VAL_ 2417487436 S2P_Bal_BalanceCircuitFault_12 0 "Nomal" 1 "Fault" ;
VAL_ 2417487436 S2P_Bal_CSCSourceVoltFault_12 0 "Nomal" 1 "Fault" ;
VAL_ 2417487436 S2P_Bal_CellVoltOverFault_12 0 "Nomal" 1 "Fault" ;
VAL_ 2417487436 S2P_Bal_CellVoltLowFault_12 0 "Nomal" 1 "Fault" ;
VAL_ 2417487436 S2P_Bal_CSCPCBTempFault_12 0 "Nomal" 1 "Fault" ;
VAL_ 2417487436 S2P_Bal_CSCSourceCurrLowFault_12 0 "Nomal" 1 "Fault" ;
VAL_ 2417487436 S2P_Bal_CSCSourceCurrOvrFault_12 0 "Nomal" 1 "Fault" ;
VAL_ 2417487437 S2P_Bal_CSCNum_13 0 "No CSC" 1 "CSC 1" 2 "CSC 2" 3 "CSC 3" 4 "CSC 4" 5 "CSC 5" 6 "CSC 6" 7 "CSC 7" 8 "CSC 8" 9 "CSC 9" 10 "CSC 10" 11 "CSC 11" 12 "CSC 12" 13 "CSC 13" 14 "CSC 14" 15 "CSC 15" 16 "CSC 16" 17 "CSC 17" 18 "CSC 18" 19 "CSC 19" 20 "CSC 20" 21 "CSC 21" 22 "CSC 22" 23 "CSC 23" 24 "CSC 24" 25 "CSC 25" 26 "CSC 26" 27 "CSC 27" 28 "CSC 28" 29 "CSC 29" 30 "CSC 30" 31 "CSC 31" ;
VAL_ 2417487437 S2P_Bal_CellNum_13 1 "Cell 1" 2 "Cell 2" 3 "Cell 3" 4 "Cell 4" 5 "Cell 5" 6 "Cell 6" 7 "Cell 7" 8 "Cell 8" 9 "Cell 9" 10 "Cell 10" 11 "Cell 11" 12 "Cell 12" 13 "Cell 13" 14 "Cell 14" 15 "Cell 15" 16 "Cell 16" 63 "Null" ;
VAL_ 2417487437 S2P_Bal_Type_13 0 "Balance stop" 1 "charge Balance" 2 "discharge Balance" ;
VAL_ 2417487437 S2P_Bal_TypeLevel_13 0 "Not Balance" 1 "Low end Balance" 2 "High end Balance" 3 "Force Balance" ;
VAL_ 2417487437 S2P_Bal_SystemStatus_13 0 "Not Static" 1 "Staic Balance" 2 "Discharge false Balance" ;
VAL_ 2417487437 S2P_Bal_Strategy_13 0 "Active Balance" 1 "Passive Static" ;
VAL_ 2417487437 S2P_Bal_ForceBalMode_13 1 "Base on time " 2 "Base on Target Vol" 3 "Base on Ave Vol" ;
VAL_ 2417487437 S2P_Bal_CellTempFault_13 0 "Nomal" 1 "Fault" ;
VAL_ 2417487437 S2P_Bal_CellVoltFail_13 0 "Nomal" 1 "Fault" ;
VAL_ 2417487437 S2P_Bal_CloseBalInstruct_13 0 "Nomal" 1 "Fault" ;
VAL_ 2417487437 S2P_Bal_CCanTimeOut_13 0 "Nomal" 1 "Fault" ;
VAL_ 2417487437 S2P_Bal_CellOffLine_13 0 "Nomal" 1 "Fault" ;
VAL_ 2417487437 S2P_Bal_BalanceCircuitFault_13 0 "Nomal" 1 "Fault" ;
VAL_ 2417487437 S2P_Bal_CSCSourceVoltFault_13 0 "Nomal" 1 "Fault" ;
VAL_ 2417487437 S2P_Bal_CellVoltOverFault_13 0 "Nomal" 1 "Fault" ;
VAL_ 2417487437 S2P_Bal_CellVoltLowFault_13 0 "Nomal" 1 "Fault" ;
VAL_ 2417487437 S2P_Bal_CSCPCBTempFault_13 0 "Nomal" 1 "Fault" ;
VAL_ 2417487437 S2P_Bal_CSCSourceCurrLowFault_13 0 "Nomal" 1 "Fault" ;
VAL_ 2417487437 S2P_Bal_CSCSourceCurrOvrFault_13 0 "Nomal" 1 "Fault" ;
VAL_ 2417487438 S2P_Bal_CSCNum_14 0 "No CSC" 1 "CSC 1" 2 "CSC 2" 3 "CSC 3" 4 "CSC 4" 5 "CSC 5" 6 "CSC 6" 7 "CSC 7" 8 "CSC 8" 9 "CSC 9" 10 "CSC 10" 11 "CSC 11" 12 "CSC 12" 13 "CSC 13" 14 "CSC 14" 15 "CSC 15" 16 "CSC 16" 17 "CSC 17" 18 "CSC 18" 19 "CSC 19" 20 "CSC 20" 21 "CSC 21" 22 "CSC 22" 23 "CSC 23" 24 "CSC 24" 25 "CSC 25" 26 "CSC 26" 27 "CSC 27" 28 "CSC 28" 29 "CSC 29" 30 "CSC 30" 31 "CSC 31" ;
VAL_ 2417487438 S2P_Bal_CellNum_14 1 "Cell 1" 2 "Cell 2" 3 "Cell 3" 4 "Cell 4" 5 "Cell 5" 6 "Cell 6" 7 "Cell 7" 8 "Cell 8" 9 "Cell 9" 10 "Cell 10" 11 "Cell 11" 12 "Cell 12" 13 "Cell 13" 14 "Cell 14" 15 "Cell 15" 16 "Cell 16" 63 "Null" ;
VAL_ 2417487438 S2P_Bal_Type_14 0 "Balance stop" 1 "charge Balance" 2 "discharge Balance" ;
VAL_ 2417487438 S2P_Bal_TypeLevel_14 0 "Not Balance" 1 "Low end Balance" 2 "High end Balance" 3 "Force Balance" ;
VAL_ 2417487438 S2P_Bal_SystemStatus_14 0 "Not Static" 1 "Staic Balance" 2 "Discharge false Balance" ;
VAL_ 2417487438 S2P_Bal_Strategy_14 0 "Active Balance" 1 "Passive Static" ;
VAL_ 2417487438 S2P_Bal_ForceBalMode_14 1 "Base on time " 2 "Base on Target Vol" 3 "Base on Ave Vol" ;
VAL_ 2417487438 S2P_Bal_CellTempFault_14 0 "Nomal" 1 "Fault" ;
VAL_ 2417487438 S2P_Bal_CellVoltFail_14 0 "Nomal" 1 "Fault" ;
VAL_ 2417487438 S2P_Bal_CloseBalInstruct_14 0 "Nomal" 1 "Fault" ;
VAL_ 2417487438 S2P_Bal_CCanTimeOut_14 0 "Nomal" 1 "Fault" ;
VAL_ 2417487438 S2P_Bal_CellOffLine_14 0 "Nomal" 1 "Fault" ;
VAL_ 2417487438 S2P_Bal_BalanceCircuitFault_14 0 "Nomal" 1 "Fault" ;
VAL_ 2417487438 S2P_Bal_CSCSourceVoltFault_14 0 "Nomal" 1 "Fault" ;
VAL_ 2417487438 S2P_Bal_CellVoltOverFault_14 0 "Nomal" 1 "Fault" ;
VAL_ 2417487438 S2P_Bal_CellVoltLowFault_14 0 "Nomal" 1 "Fault" ;
VAL_ 2417487438 S2P_Bal_CSCPCBTempFault_14 0 "Nomal" 1 "Fault" ;
VAL_ 2417487438 S2P_Bal_CSCSourceCurrLowFault_14 0 "Nomal" 1 "Fault" ;
VAL_ 2417487438 S2P_Bal_CSCSourceCurrOvrFault_14 0 "Nomal" 1 "Fault" ;
VAL_ 2417487439 S2P_Bal_CSCNum_15 0 "No CSC" 1 "CSC 1" 2 "CSC 2" 3 "CSC 3" 4 "CSC 4" 5 "CSC 5" 6 "CSC 6" 7 "CSC 7" 8 "CSC 8" 9 "CSC 9" 10 "CSC 10" 11 "CSC 11" 12 "CSC 12" 13 "CSC 13" 14 "CSC 14" 15 "CSC 15" 16 "CSC 16" 17 "CSC 17" 18 "CSC 18" 19 "CSC 19" 20 "CSC 20" 21 "CSC 21" 22 "CSC 22" 23 "CSC 23" 24 "CSC 24" 25 "CSC 25" 26 "CSC 26" 27 "CSC 27" 28 "CSC 28" 29 "CSC 29" 30 "CSC 30" 31 "CSC 31" ;
VAL_ 2417487439 S2P_Bal_CellNum_15 1 "Cell 1" 2 "Cell 2" 3 "Cell 3" 4 "Cell 4" 5 "Cell 5" 6 "Cell 6" 7 "Cell 7" 8 "Cell 8" 9 "Cell 9" 10 "Cell 10" 11 "Cell 11" 12 "Cell 12" 13 "Cell 13" 14 "Cell 14" 15 "Cell 15" 16 "Cell 16" 63 "Null" ;
VAL_ 2417487439 S2P_Bal_Type_15 0 "Balance stop" 1 "charge Balance" 2 "discharge Balance" ;
VAL_ 2417487439 S2P_Bal_TypeLevel_15 0 "Not Balance" 1 "Low end Balance" 2 "High end Balance" 3 "Force Balance" ;
VAL_ 2417487439 S2P_Bal_SystemStatus_15 0 "Not Static" 1 "Staic Balance" 2 "Discharge false Balance" ;
VAL_ 2417487439 S2P_Bal_Strategy_15 0 "Active Balance" 1 "Passive Static" ;
VAL_ 2417487439 S2P_Bal_ForceBalMode_15 1 "Base on time " 2 "Base on Target Vol" 3 "Base on Ave Vol" ;
VAL_ 2417487439 S2P_Bal_CellTempFault_15 0 "Nomal" 1 "Fault" ;
VAL_ 2417487439 S2P_Bal_CellVoltFail_15 0 "Nomal" 1 "Fault" ;
VAL_ 2417487439 S2P_Bal_CloseBalInstruct_15 0 "Nomal" 1 "Fault" ;
VAL_ 2417487439 S2P_Bal_CCanTimeOut_15 0 "Nomal" 1 "Fault" ;
VAL_ 2417487439 S2P_Bal_CellOffLine_15 0 "Nomal" 1 "Fault" ;
VAL_ 2417487439 S2P_Bal_BalanceCircuitFault_15 0 "Nomal" 1 "Fault" ;
VAL_ 2417487439 S2P_Bal_CSCSourceVoltFault_15 0 "Nomal" 1 "Fault" ;
VAL_ 2417487439 S2P_Bal_CellVoltOverFault_15 0 "Nomal" 1 "Fault" ;
VAL_ 2417487439 S2P_Bal_CellVoltLowFault_15 0 "Nomal" 1 "Fault" ;
VAL_ 2417487439 S2P_Bal_CSCPCBTempFault_15 0 "Nomal" 1 "Fault" ;
VAL_ 2417487439 S2P_Bal_CSCSourceCurrLowFault_15 0 "Nomal" 1 "Fault" ;
VAL_ 2417487439 S2P_Bal_CSCSourceCurrOvrFault_15 0 "Nomal" 1 "Fault" ;
VAL_ 2417487440 S2P_Bal_CSCNum_16 0 "No CSC" 1 "CSC 1" 2 "CSC 2" 3 "CSC 3" 4 "CSC 4" 5 "CSC 5" 6 "CSC 6" 7 "CSC 7" 8 "CSC 8" 9 "CSC 9" 10 "CSC 10" 11 "CSC 11" 12 "CSC 12" 13 "CSC 13" 14 "CSC 14" 15 "CSC 15" 16 "CSC 16" 17 "CSC 17" 18 "CSC 18" 19 "CSC 19" 20 "CSC 20" 21 "CSC 21" 22 "CSC 22" 23 "CSC 23" 24 "CSC 24" 25 "CSC 25" 26 "CSC 26" 27 "CSC 27" 28 "CSC 28" 29 "CSC 29" 30 "CSC 30" 31 "CSC 31" ;
VAL_ 2417487440 S2P_Bal_CellNum_16 1 "Cell 1" 2 "Cell 2" 3 "Cell 3" 4 "Cell 4" 5 "Cell 5" 6 "Cell 6" 7 "Cell 7" 8 "Cell 8" 9 "Cell 9" 10 "Cell 10" 11 "Cell 11" 12 "Cell 12" 13 "Cell 13" 14 "Cell 14" 15 "Cell 15" 16 "Cell 16" 63 "Null" ;
VAL_ 2417487440 S2P_Bal_Type_16 0 "Balance stop" 1 "charge Balance" 2 "discharge Balance" ;
VAL_ 2417487440 S2P_Bal_TypeLevel_16 0 "Not Balance" 1 "Low end Balance" 2 "High end Balance" 3 "Force Balance" ;
VAL_ 2417487440 S2P_Bal_SystemStatus_16 0 "Not Static" 1 "Staic Balance" 2 "Discharge false Balance" ;
VAL_ 2417487440 S2P_Bal_Strategy_16 0 "Active Balance" 1 "Passive Static" ;
VAL_ 2417487440 S2P_Bal_ForceBalMode_16 1 "Base on time " 2 "Base on Target Vol" 3 "Base on Ave Vol" ;
VAL_ 2417487440 S2P_Bal_CellTempFault_16 0 "Nomal" 1 "Fault" ;
VAL_ 2417487440 S2P_Bal_CellVoltFail_16 0 "Nomal" 1 "Fault" ;
VAL_ 2417487440 S2P_Bal_CloseBalInstruct_16 0 "Nomal" 1 "Fault" ;
VAL_ 2417487440 S2P_Bal_CCanTimeOut_16 0 "Nomal" 1 "Fault" ;
VAL_ 2417487440 S2P_Bal_CellOffLine_16 0 "Nomal" 1 "Fault" ;
VAL_ 2417487440 S2P_Bal_BalanceCircuitFault_16 0 "Nomal" 1 "Fault" ;
VAL_ 2417487440 S2P_Bal_CSCSourceVoltFault_16 0 "Nomal" 1 "Fault" ;
VAL_ 2417487440 S2P_Bal_CellVoltOverFault_16 0 "Nomal" 1 "Fault" ;
VAL_ 2417487440 S2P_Bal_CellVoltLowFault_16 0 "Nomal" 1 "Fault" ;
VAL_ 2417487440 S2P_Bal_CSCPCBTempFault_16 0 "Nomal" 1 "Fault" ;
VAL_ 2417487440 S2P_Bal_CSCSourceCurrLowFault_16 0 "Nomal" 1 "Fault" ;
VAL_ 2417487440 S2P_Bal_CSCSourceCurrOvrFault_16 0 "Nomal" 1 "Fault" ;
VAL_ 2417487441 S2P_Bal_CSCNum_17 0 "No CSC" 1 "CSC 1" 2 "CSC 2" 3 "CSC 3" 4 "CSC 4" 5 "CSC 5" 6 "CSC 6" 7 "CSC 7" 8 "CSC 8" 9 "CSC 9" 10 "CSC 10" 11 "CSC 11" 12 "CSC 12" 13 "CSC 13" 14 "CSC 14" 15 "CSC 15" 16 "CSC 16" 17 "CSC 17" 18 "CSC 18" 19 "CSC 19" 20 "CSC 20" 21 "CSC 21" 22 "CSC 22" 23 "CSC 23" 24 "CSC 24" 25 "CSC 25" 26 "CSC 26" 27 "CSC 27" 28 "CSC 28" 29 "CSC 29" 30 "CSC 30" 31 "CSC 31" ;
VAL_ 2417487441 S2P_Bal_CellNum_17 1 "Cell 1" 2 "Cell 2" 3 "Cell 3" 4 "Cell 4" 5 "Cell 5" 6 "Cell 6" 7 "Cell 7" 8 "Cell 8" 9 "Cell 9" 10 "Cell 10" 11 "Cell 11" 12 "Cell 12" 13 "Cell 13" 14 "Cell 14" 15 "Cell 15" 16 "Cell 16" 63 "Null" ;
VAL_ 2417487441 S2P_Bal_Type_17 0 "Balance stop" 1 "charge Balance" 2 "discharge Balance" ;
VAL_ 2417487441 S2P_Bal_TypeLevel_17 0 "Not Balance" 1 "Low end Balance" 2 "High end Balance" 3 "Force Balance" ;
VAL_ 2417487441 S2P_Bal_SystemStatus_17 0 "Not Static" 1 "Staic Balance" 2 "Discharge false Balance" ;
VAL_ 2417487441 S2P_Bal_Strategy_17 0 "Active Balance" 1 "Passive Static" ;
VAL_ 2417487441 S2P_Bal_ForceBalMode_17 1 "Base on time " 2 "Base on Target Vol" 3 "Base on Ave Vol" ;
VAL_ 2417487441 S2P_Bal_CellTempFault_17 0 "Nomal" 1 "Fault" ;
VAL_ 2417487441 S2P_Bal_CellVoltFail_17 0 "Nomal" 1 "Fault" ;
VAL_ 2417487441 S2P_Bal_CloseBalInstruct_17 0 "Nomal" 1 "Fault" ;
VAL_ 2417487441 S2P_Bal_CCanTimeOut_17 0 "Nomal" 1 "Fault" ;
VAL_ 2417487441 S2P_Bal_CellOffLine_17 0 "Nomal" 1 "Fault" ;
VAL_ 2417487441 S2P_Bal_BalanceCircuitFault_17 0 "Nomal" 1 "Fault" ;
VAL_ 2417487441 S2P_Bal_CSCSourceVoltFault_17 0 "Nomal" 1 "Fault" ;
VAL_ 2417487441 S2P_Bal_CellVoltOverFault_17 0 "Nomal" 1 "Fault" ;
VAL_ 2417487441 S2P_Bal_CellVoltLowFault_17 0 "Nomal" 1 "Fault" ;
VAL_ 2417487441 S2P_Bal_CSCPCBTempFault_17 0 "Nomal" 1 "Fault" ;
VAL_ 2417487441 S2P_Bal_CSCSourceCurrLowFault_17 0 "Nomal" 1 "Fault" ;
VAL_ 2417487441 S2P_Bal_CSCSourceCurrOvrFault_17 0 "Nomal" 1 "Fault" ;
VAL_ 2417487442 S2P_Bal_CSCNum_18 0 "No CSC" 1 "CSC 1" 2 "CSC 2" 3 "CSC 3" 4 "CSC 4" 5 "CSC 5" 6 "CSC 6" 7 "CSC 7" 8 "CSC 8" 9 "CSC 9" 10 "CSC 10" 11 "CSC 11" 12 "CSC 12" 13 "CSC 13" 14 "CSC 14" 15 "CSC 15" 16 "CSC 16" 17 "CSC 17" 18 "CSC 18" 19 "CSC 19" 20 "CSC 20" 21 "CSC 21" 22 "CSC 22" 23 "CSC 23" 24 "CSC 24" 25 "CSC 25" 26 "CSC 26" 27 "CSC 27" 28 "CSC 28" 29 "CSC 29" 30 "CSC 30" 31 "CSC 31" ;
VAL_ 2417487442 S2P_Bal_CellNum_18 1 "Cell 1" 2 "Cell 2" 3 "Cell 3" 4 "Cell 4" 5 "Cell 5" 6 "Cell 6" 7 "Cell 7" 8 "Cell 8" 9 "Cell 9" 10 "Cell 10" 11 "Cell 11" 12 "Cell 12" 13 "Cell 13" 14 "Cell 14" 15 "Cell 15" 16 "Cell 16" 63 "Null" ;
VAL_ 2417487442 S2P_Bal_Type_18 0 "Balance stop" 1 "charge Balance" 2 "discharge Balance" ;
VAL_ 2417487442 S2P_Bal_TypeLevel_18 0 "Not Balance" 1 "Low end Balance" 2 "High end Balance" 3 "Force Balance" ;
VAL_ 2417487442 S2P_Bal_SystemStatus_18 0 "Not Static" 1 "Staic Balance" 2 "Discharge false Balance" ;
VAL_ 2417487442 S2P_Bal_Strategy_18 0 "Active Balance" 1 "Passive Static" ;
VAL_ 2417487442 S2P_Bal_ForceBalMode_18 1 "Base on time " 2 "Base on Target Vol" 3 "Base on Ave Vol" ;
VAL_ 2417487442 S2P_Bal_CellTempFault_18 0 "Nomal" 1 "Fault" ;
VAL_ 2417487442 S2P_Bal_CellVoltFail_18 0 "Nomal" 1 "Fault" ;
VAL_ 2417487442 S2P_Bal_CloseBalInstruct_18 0 "Nomal" 1 "Fault" ;
VAL_ 2417487442 S2P_Bal_CCanTimeOut_18 0 "Nomal" 1 "Fault" ;
VAL_ 2417487442 S2P_Bal_CellOffLine_18 0 "Nomal" 1 "Fault" ;
VAL_ 2417487442 S2P_Bal_BalanceCircuitFault_18 0 "Nomal" 1 "Fault" ;
VAL_ 2417487442 S2P_Bal_CSCSourceVoltFault_18 0 "Nomal" 1 "Fault" ;
VAL_ 2417487442 S2P_Bal_CellVoltOverFault_18 0 "Nomal" 1 "Fault" ;
VAL_ 2417487442 S2P_Bal_CellVoltLowFault_18 0 "Nomal" 1 "Fault" ;
VAL_ 2417487442 S2P_Bal_CSCPCBTempFault_18 0 "Nomal" 1 "Fault" ;
VAL_ 2417487442 S2P_Bal_CSCSourceCurrLowFault_18 0 "Nomal" 1 "Fault" ;
VAL_ 2417487442 S2P_Bal_CSCSourceCurrOvrFault_18 0 "Nomal" 1 "Fault" ;
VAL_ 2417487443 S2P_Bal_CSCNum_19 0 "No CSC" 1 "CSC 1" 2 "CSC 2" 3 "CSC 3" 4 "CSC 4" 5 "CSC 5" 6 "CSC 6" 7 "CSC 7" 8 "CSC 8" 9 "CSC 9" 10 "CSC 10" 11 "CSC 11" 12 "CSC 12" 13 "CSC 13" 14 "CSC 14" 15 "CSC 15" 16 "CSC 16" 17 "CSC 17" 18 "CSC 18" 19 "CSC 19" 20 "CSC 20" 21 "CSC 21" 22 "CSC 22" 23 "CSC 23" 24 "CSC 24" 25 "CSC 25" 26 "CSC 26" 27 "CSC 27" 28 "CSC 28" 29 "CSC 29" 30 "CSC 30" 31 "CSC 31" ;
VAL_ 2417487443 S2P_Bal_CellNum_19 1 "Cell 1" 2 "Cell 2" 3 "Cell 3" 4 "Cell 4" 5 "Cell 5" 6 "Cell 6" 7 "Cell 7" 8 "Cell 8" 9 "Cell 9" 10 "Cell 10" 11 "Cell 11" 12 "Cell 12" 13 "Cell 13" 14 "Cell 14" 15 "Cell 15" 16 "Cell 16" 63 "Null" ;
VAL_ 2417487443 S2P_Bal_Type_19 0 "Balance stop" 1 "charge Balance" 2 "discharge Balance" ;
VAL_ 2417487443 S2P_Bal_TypeLevel_19 0 "Not Balance" 1 "Low end Balance" 2 "High end Balance" 3 "Force Balance" ;
VAL_ 2417487443 S2P_Bal_SystemStatus_19 0 "Not Static" 1 "Staic Balance" 2 "Discharge false Balance" ;
VAL_ 2417487443 S2P_Bal_Strategy_19 0 "Active Balance" 1 "Passive Static" ;
VAL_ 2417487443 S2P_Bal_ForceBalMode_19 1 "Base on time " 2 "Base on Target Vol" 3 "Base on Ave Vol" ;
VAL_ 2417487443 S2P_Bal_CellTempFault_19 0 "Nomal" 1 "Fault" ;
VAL_ 2417487443 S2P_Bal_CellVoltFail_19 0 "Nomal" 1 "Fault" ;
VAL_ 2417487443 S2P_Bal_CloseBalInstruct_19 0 "Nomal" 1 "Fault" ;
VAL_ 2417487443 S2P_Bal_CCanTimeOut_19 0 "Nomal" 1 "Fault" ;
VAL_ 2417487443 S2P_Bal_CellOffLine_19 0 "Nomal" 1 "Fault" ;
VAL_ 2417487443 S2P_Bal_BalanceCircuitFault_19 0 "Nomal" 1 "Fault" ;
VAL_ 2417487443 S2P_Bal_CSCSourceVoltFault_19 0 "Nomal" 1 "Fault" ;
VAL_ 2417487443 S2P_Bal_CellVoltOverFault_19 0 "Nomal" 1 "Fault" ;
VAL_ 2417487443 S2P_Bal_CellVoltLowFault_19 0 "Nomal" 1 "Fault" ;
VAL_ 2417487443 S2P_Bal_CSCPCBTempFault_19 0 "Nomal" 1 "Fault" ;
VAL_ 2417487443 S2P_Bal_CSCSourceCurrLowFault_19 0 "Nomal" 1 "Fault" ;
VAL_ 2417487443 S2P_Bal_CSCSourceCurrOvrFault_19 0 "Nomal" 1 "Fault" ;
VAL_ 2417487444 S2P_Bal_CSCNum_20 0 "No CSC" 1 "CSC 1" 2 "CSC 2" 3 "CSC 3" 4 "CSC 4" 5 "CSC 5" 6 "CSC 6" 7 "CSC 7" 8 "CSC 8" 9 "CSC 9" 10 "CSC 10" 11 "CSC 11" 12 "CSC 12" 13 "CSC 13" 14 "CSC 14" 15 "CSC 15" 16 "CSC 16" 17 "CSC 17" 18 "CSC 18" 19 "CSC 19" 20 "CSC 20" 21 "CSC 21" 22 "CSC 22" 23 "CSC 23" 24 "CSC 24" 25 "CSC 25" 26 "CSC 26" 27 "CSC 27" 28 "CSC 28" 29 "CSC 29" 30 "CSC 30" 31 "CSC 31" ;
VAL_ 2417487444 S2P_Bal_CellNum_20 1 "Cell 1" 2 "Cell 2" 3 "Cell 3" 4 "Cell 4" 5 "Cell 5" 6 "Cell 6" 7 "Cell 7" 8 "Cell 8" 9 "Cell 9" 10 "Cell 10" 11 "Cell 11" 12 "Cell 12" 13 "Cell 13" 14 "Cell 14" 15 "Cell 15" 16 "Cell 16" 63 "Null" ;
VAL_ 2417487444 S2P_Bal_Type_20 0 "Balance stop" 1 "charge Balance" 2 "discharge Balance" ;
VAL_ 2417487444 S2P_Bal_TypeLevel_20 0 "Not Balance" 1 "Low end Balance" 2 "High end Balance" 3 "Force Balance" ;
VAL_ 2417487444 S2P_Bal_SystemStatus_20 0 "Not Static" 1 "Staic Balance" 2 "Discharge false Balance" ;
VAL_ 2417487444 S2P_Bal_Strategy_20 0 "Active Balance" 1 "Passive Static" ;
VAL_ 2417487444 S2P_Bal_ForceBalMode_20 1 "Base on time " 2 "Base on Target Vol" 3 "Base on Ave Vol" ;
VAL_ 2417487444 S2P_Bal_CellTempFault_20 0 "Nomal" 1 "Fault" ;
VAL_ 2417487444 S2P_Bal_CellVoltFail_20 0 "Nomal" 1 "Fault" ;
VAL_ 2417487444 S2P_Bal_CloseBalInstruct_20 0 "Nomal" 1 "Fault" ;
VAL_ 2417487444 S2P_Bal_CCanTimeOut_20 0 "Nomal" 1 "Fault" ;
VAL_ 2417487444 S2P_Bal_CellOffLine_20 0 "Nomal" 1 "Fault" ;
VAL_ 2417487444 S2P_Bal_BalanceCircuitFault_20 0 "Nomal" 1 "Fault" ;
VAL_ 2417487444 S2P_Bal_CSCSourceVoltFault_20 0 "Nomal" 1 "Fault" ;
VAL_ 2417487444 S2P_Bal_CellVoltOverFault_20 0 "Nomal" 1 "Fault" ;
VAL_ 2417487444 S2P_Bal_CellVoltLowFault_20 0 "Nomal" 1 "Fault" ;
VAL_ 2417487444 S2P_Bal_CSCPCBTempFault_20 0 "Nomal" 1 "Fault" ;
VAL_ 2417487444 S2P_Bal_CSCSourceCurrLowFault_20 0 "Nomal" 1 "Fault" ;
VAL_ 2417487444 S2P_Bal_CSCSourceCurrOvrFault_20 0 "Nomal" 1 "Fault" ;
VAL_ 2417487445 S2P_Bal_CSCNum_21 0 "No CSC" 1 "CSC 1" 2 "CSC 2" 3 "CSC 3" 4 "CSC 4" 5 "CSC 5" 6 "CSC 6" 7 "CSC 7" 8 "CSC 8" 9 "CSC 9" 10 "CSC 10" 11 "CSC 11" 12 "CSC 12" 13 "CSC 13" 14 "CSC 14" 15 "CSC 15" 16 "CSC 16" 17 "CSC 17" 18 "CSC 18" 19 "CSC 19" 20 "CSC 20" 21 "CSC 21" 22 "CSC 22" 23 "CSC 23" 24 "CSC 24" 25 "CSC 25" 26 "CSC 26" 27 "CSC 27" 28 "CSC 28" 29 "CSC 29" 30 "CSC 30" 31 "CSC 31" ;
VAL_ 2417487445 S2P_Bal_CellNum_21 1 "Cell 1" 2 "Cell 2" 3 "Cell 3" 4 "Cell 4" 5 "Cell 5" 6 "Cell 6" 7 "Cell 7" 8 "Cell 8" 9 "Cell 9" 10 "Cell 10" 11 "Cell 11" 12 "Cell 12" 13 "Cell 13" 14 "Cell 14" 15 "Cell 15" 16 "Cell 16" 63 "Null" ;
VAL_ 2417487445 S2P_Bal_Type_21 0 "Balance stop" 1 "charge Balance" 2 "discharge Balance" ;
VAL_ 2417487445 S2P_Bal_TypeLevel_21 0 "Not Balance" 1 "Low end Balance" 2 "High end Balance" 3 "Force Balance" ;
VAL_ 2417487445 S2P_Bal_SystemStatus_21 0 "Not Static" 1 "Staic Balance" 2 "Discharge false Balance" ;
VAL_ 2417487445 S2P_Bal_Strategy_21 0 "Active Balance" 1 "Passive Static" ;
VAL_ 2417487445 S2P_Bal_ForceBalMode_21 1 "Base on time " 2 "Base on Target Vol" 3 "Base on Ave Vol" ;
VAL_ 2417487445 S2P_Bal_CellTempFault_21 0 "Nomal" 1 "Fault" ;
VAL_ 2417487445 S2P_Bal_CellVoltFail_21 0 "Nomal" 1 "Fault" ;
VAL_ 2417487445 S2P_Bal_CloseBalInstruct_21 0 "Nomal" 1 "Fault" ;
VAL_ 2417487445 S2P_Bal_CCanTimeOut_21 0 "Nomal" 1 "Fault" ;
VAL_ 2417487445 S2P_Bal_CellOffLine_21 0 "Nomal" 1 "Fault" ;
VAL_ 2417487445 S2P_Bal_BalanceCircuitFault_21 0 "Nomal" 1 "Fault" ;
VAL_ 2417487445 S2P_Bal_CSCSourceVoltFault_21 0 "Nomal" 1 "Fault" ;
VAL_ 2417487445 S2P_Bal_CellVoltOverFault_21 0 "Nomal" 1 "Fault" ;
VAL_ 2417487445 S2P_Bal_CellVoltLowFault_21 0 "Nomal" 1 "Fault" ;
VAL_ 2417487445 S2P_Bal_CSCPCBTempFault_21 0 "Nomal" 1 "Fault" ;
VAL_ 2417487445 S2P_Bal_CSCSourceCurrLowFault_21 0 "Nomal" 1 "Fault" ;
VAL_ 2417487445 S2P_Bal_CSCSourceCurrOvrFault_21 0 "Nomal" 1 "Fault" ;
VERSION ""

NS_ :

BS_:

BU_: MBMU PC SBMU IMM ETH DCDC LEMS

BO_ 2417487446 S2P_BL_Meg__22: 8 SBMU
 SG_ S2P_Bal_CSCNum_22 : 0|6@1+ (1,0) [0|63] ""  PC
 SG_ S2P_Bal_CellNum_22 : 6|6@1+ (1,0) [0|63] ""  PC
 SG_ S2P_Bal_Type_22 : 12|2@1+ (1,0) [0|3] ""  PC
 SG_ S2P_Bal_TimeRemain_22 : 14|9@1+ (1,0) [0|511] ""  PC
 SG_ S2P_Bal_DeltaVolt_22 : 23|10@1+ (1,0) [0|1023] ""  PC
 SG_ S2P_Bal_CSCPowerCurr_22 : 33|11@1+ (1,0) [0|2047] ""  PC
 SG_ S2P_Bal_TypeLevel_22 : 44|3@1+ (1,0) [0|7] ""  PC
 SG_ S2P_Bal_SystemStatus_22 : 47|2@1+ (1,0) [0|3] ""  PC
 SG_ S2P_Bal_Strategy_22 : 49|1@1+ (1,0) [0|1] ""  PC
 SG_ S2P_Bal_ForceBalMode_22 : 50|2@1+ (1,0) [0|3] ""  PC
 SG_ S2P_Bal_CellTempFault_22 : 52|1@1+ (1,0) [0|1] ""  PC
 SG_ S2P_Bal_CellVoltFail_22 : 53|1@1+ (1,0) [0|1] ""  PC
 SG_ S2P_Bal_CloseBalInstruct_22 : 54|1@1+ (1,0) [0|1] ""  PC
 SG_ S2P_Bal_CCanTimeOut_22 : 55|1@1+ (1,0) [0|1] ""  PC
 SG_ S2P_Bal_CellOffLine_22 : 56|1@1+ (1,0) [0|1] ""  PC
 SG_ S2P_Bal_BalanceCircuitFault_22 : 57|1@1+ (1,0) [0|1] ""  PC
 SG_ S2P_Bal_CSCSourceVoltFault_22 : 58|1@1+ (1,0) [0|1] ""  PC
 SG_ S2P_Bal_CellVoltOverFault_22 : 59|1@1+ (1,0) [0|1] ""  PC
 SG_ S2P_Bal_CellVoltLowFault_22 : 60|1@1+ (1,0) [0|1] ""  PC
 SG_ S2P_Bal_CSCPCBTempFault_22 : 61|1@1+ (1,0) [0|1] ""  PC
 SG_ S2P_Bal_CSCSourceCurrLowFault_22 : 62|1@1+ (1,0) [0|1] ""  PC
 SG_ S2P_Bal_CSCSourceCurrOvrFault_22 : 63|1@1+ (1,0) [0|1] ""  PC

BO_ 2417487447 S2P_BL_Meg__23: 8 SBMU
 SG_ S2P_Bal_CSCNum_23 : 0|6@1+ (1,0) [0|63] ""  PC
 SG_ S2P_Bal_CellNum_23 : 6|6@1+ (1,0) [0|63] ""  PC
 SG_ S2P_Bal_Type_23 : 12|2@1+ (1,0) [0|3] ""  PC
 SG_ S2P_Bal_TimeRemain_23 : 14|9@1+ (1,0) [0|511] ""  PC
 SG_ S2P_Bal_DeltaVolt_23 : 23|10@1+ (1,0) [0|1023] ""  PC
 SG_ S2P_Bal_CSCPowerCurr_23 : 33|11@1+ (1,0) [0|2047] ""  PC
 SG_ S2P_Bal_TypeLevel_23 : 44|3@1+ (1,0) [0|7] ""  PC
 SG_ S2P_Bal_SystemStatus_23 : 47|2@1+ (1,0) [0|3] ""  PC
 SG_ S2P_Bal_Strategy_23 : 49|1@1+ (1,0) [0|1] ""  PC
 SG_ S2P_Bal_ForceBalMode_23 : 50|2@1+ (1,0) [0|3] ""  PC
 SG_ S2P_Bal_CellTempFault_23 : 52|1@1+ (1,0) [0|1] ""  PC
 SG_ S2P_Bal_CellVoltFail_23 : 53|1@1+ (1,0) [0|1] ""  PC
 SG_ S2P_Bal_CloseBalInstruct_23 : 54|1@1+ (1,0) [0|1] ""  PC
 SG_ S2P_Bal_CCanTimeOut_23 : 55|1@1+ (1,0) [0|1] ""  PC
 SG_ S2P_Bal_CellOffLine_23 : 56|1@1+ (1,0) [0|1] ""  PC
 SG_ S2P_Bal_BalanceCircuitFault_23 : 57|1@1+ (1,0) [0|1] ""  PC
 SG_ S2P_Bal_CSCSourceVoltFault_23 : 58|1@1+ (1,0) [0|1] ""  PC
 SG_ S2P_Bal_CellVoltOverFault_23 : 59|1@1+ (1,0) [0|1] ""  PC
 SG_ S2P_Bal_CellVoltLowFault_23 : 60|1@1+ (1,0) [0|1] ""  PC
 SG_ S2P_Bal_CSCPCBTempFault_23 : 61|1@1+ (1,0) [0|1] ""  PC
 SG_ S2P_Bal_CSCSourceCurrLowFault_23 : 62|1@1+ (1,0) [0|1] ""  PC
 SG_ S2P_Bal_CSCSourceCurrOvrFault_23 : 63|1@1+ (1,0) [0|1] ""  PC

BO_ 2417487448 S2P_BL_Meg__24: 8 SBMU
 SG_ S2P_Bal_CSCNum_24 : 0|6@1+ (1,0) [0|63] ""  PC
 SG_ S2P_Bal_CellNum_24 : 6|6@1+ (1,0) [0|63] ""  PC
 SG_ S2P_Bal_Type_24 : 12|2@1+ (1,0) [0|3] ""  PC
 SG_ S2P_Bal_TimeRemain_24 : 14|9@1+ (1,0) [0|511] ""  PC
 SG_ S2P_Bal_DeltaVolt_24 : 23|10@1+ (1,0) [0|1023] ""  PC
 SG_ S2P_Bal_CSCPowerCurr_24 : 33|11@1+ (1,0) [0|2047] ""  PC
 SG_ S2P_Bal_TypeLevel_24 : 44|3@1+ (1,0) [0|7] ""  PC
 SG_ S2P_Bal_SystemStatus_24 : 47|2@1+ (1,0) [0|3] ""  PC
 SG_ S2P_Bal_Strategy_24 : 49|1@1+ (1,0) [0|1] ""  PC
 SG_ S2P_Bal_ForceBalMode_24 : 50|2@1+ (1,0) [0|3] ""  PC
 SG_ S2P_Bal_CellTempFault_24 : 52|1@1+ (1,0) [0|1] ""  PC
 SG_ S2P_Bal_CellVoltFail_24 : 53|1@1+ (1,0) [0|1] ""  PC
 SG_ S2P_Bal_CloseBalInstruct_24 : 54|1@1+ (1,0) [0|1] ""  PC
 SG_ S2P_Bal_CCanTimeOut_24 : 55|1@1+ (1,0) [0|1] ""  PC
 SG_ S2P_Bal_CellOffLine_24 : 56|1@1+ (1,0) [0|1] ""  PC
 SG_ S2P_Bal_BalanceCircuitFault_24 : 57|1@1+ (1,0) [0|1] ""  PC
 SG_ S2P_Bal_CSCSourceVoltFault_24 : 58|1@1+ (1,0) [0|1] ""  PC
 SG_ S2P_Bal_CellVoltOverFault_24 : 59|1@1+ (1,0) [0|1] ""  PC
 SG_ S2P_Bal_CellVoltLowFault_24 : 60|1@1+ (1,0) [0|1] ""  PC
 SG_ S2P_Bal_CSCPCBTempFault_24 : 61|1@1+ (1,0) [0|1] ""  PC
 SG_ S2P_Bal_CSCSourceCurrLowFault_24 : 62|1@1+ (1,0) [0|1] ""  PC
 SG_ S2P_Bal_CSCSourceCurrOvrFault_24 : 63|1@1+ (1,0) [0|1] ""  PC

BO_ 2417487449 S2P_BL_Meg__25: 8 SBMU
 SG_ S2P_Bal_CSCNum_25 : 0|6@1+ (1,0) [0|63] ""  PC
 SG_ S2P_Bal_CellNum_25 : 6|6@1+ (1,0) [0|63] ""  PC
 SG_ S2P_Bal_Type_25 : 12|2@1+ (1,0) [0|3] ""  PC
 SG_ S2P_Bal_TimeRemain_25 : 14|9@1+ (1,0) [0|511] ""  PC
 SG_ S2P_Bal_DeltaVolt_25 : 23|10@1+ (1,0) [0|1023] ""  PC
 SG_ S2P_Bal_CSCPowerCurr_25 : 33|11@1+ (1,0) [0|2047] ""  PC
 SG_ S2P_Bal_TypeLevel_25 : 44|3@1+ (1,0) [0|7] ""  PC
 SG_ S2P_Bal_SystemStatus_25 : 47|2@1+ (1,0) [0|3] ""  PC
 SG_ S2P_Bal_Strategy_25 : 49|1@1+ (1,0) [0|1] ""  PC
 SG_ S2P_Bal_ForceBalMode_25 : 50|2@1+ (1,0) [0|3] ""  PC
 SG_ S2P_Bal_CellTempFault_25 : 52|1@1+ (1,0) [0|1] ""  PC
 SG_ S2P_Bal_CellVoltFail_25 : 53|1@1+ (1,0) [0|1] ""  PC
 SG_ S2P_Bal_CloseBalInstruct_25 : 54|1@1+ (1,0) [0|1] ""  PC
 SG_ S2P_Bal_CCanTimeOut_25 : 55|1@1+ (1,0) [0|1] ""  PC
 SG_ S2P_Bal_CellOffLine_25 : 56|1@1+ (1,0) [0|1] ""  PC
 SG_ S2P_Bal_BalanceCircuitFault_25 : 57|1@1+ (1,0) [0|1] ""  PC
 SG_ S2P_Bal_CSCSourceVoltFault_25 : 58|1@1+ (1,0) [0|1] ""  PC
 SG_ S2P_Bal_CellVoltOverFault_25 : 59|1@1+ (1,0) [0|1] ""  PC
 SG_ S2P_Bal_CellVoltLowFault_25 : 60|1@1+ (1,0) [0|1] ""  PC
 SG_ S2P_Bal_CSCPCBTempFault_25 : 61|1@1+ (1,0) [0|1] ""  PC
 SG_ S2P_Bal_CSCSourceCurrLowFault_25 : 62|1@1+ (1,0) [0|1] ""  PC
 SG_ S2P_Bal_CSCSourceCurrOvrFault_25 : 63|1@1+ (1,0) [0|1] ""  PC

BO_ 2417487450 S2P_BL_Meg__26: 8 SBMU
 SG_ S2P_Bal_CSCNum_26 : 0|6@1+ (1,0) [0|63] ""  PC
 SG_ S2P_Bal_CellNum_26 : 6|6@1+ (1,0) [0|63] ""  PC
 SG_ S2P_Bal_Type_26 : 12|2@1+ (1,0) [0|3] ""  PC
 SG_ S2P_Bal_TimeRemain_26 : 14|9@1+ (1,0) [0|511] ""  PC
 SG_ S2P_Bal_DeltaVolt_26 : 23|10@1+ (1,0) [0|1023] ""  PC
 SG_ S2P_Bal_CSCPowerCurr_26 : 33|11@1+ (1,0) [0|2047] ""  PC
 SG_ S2P_Bal_TypeLevel_26 : 44|3@1+ (1,0) [0|7] ""  PC
 SG_ S2P_Bal_SystemStatus_26 : 47|2@1+ (1,0) [0|3] ""  PC
 SG_ S2P_Bal_Strategy_26 : 49|1@1+ (1,0) [0|1] ""  PC
 SG_ S2P_Bal_ForceBalMode_26 : 50|2@1+ (1,0) [0|3] ""  PC
 SG_ S2P_Bal_CellTempFault_26 : 52|1@1+ (1,0) [0|1] ""  PC
 SG_ S2P_Bal_CellVoltFail_26 : 53|1@1+ (1,0) [0|1] ""  PC
 SG_ S2P_Bal_CloseBalInstruct_26 : 54|1@1+ (1,0) [0|1] ""  PC
 SG_ S2P_Bal_CCanTimeOut_26 : 55|1@1+ (1,0) [0|1] ""  PC
 SG_ S2P_Bal_CellOffLine_26 : 56|1@1+ (1,0) [0|1] ""  PC
 SG_ S2P_Bal_BalanceCircuitFault_26 : 57|1@1+ (1,0) [0|1] ""  PC
 SG_ S2P_Bal_CSCSourceVoltFault_26 : 58|1@1+ (1,0) [0|1] ""  PC
 SG_ S2P_Bal_CellVoltOverFault_26 : 59|1@1+ (1,0) [0|1] ""  PC
 SG_ S2P_Bal_CellVoltLowFault_26 : 60|1@1+ (1,0) [0|1] ""  PC
 SG_ S2P_Bal_CSCPCBTempFault_26 : 61|1@1+ (1,0) [0|1] ""  PC
 SG_ S2P_Bal_CSCSourceCurrLowFault_26 : 62|1@1+ (1,0) [0|1] ""  PC
 SG_ S2P_Bal_CSCSourceCurrOvrFault_26 : 63|1@1+ (1,0) [0|1] ""  PC

BO_ 2417487451 S2P_BL_Meg__27: 8 SBMU
 SG_ S2P_Bal_CSCNum_27 : 0|6@1+ (1,0) [0|63] ""  PC
 SG_ S2P_Bal_CellNum_27 : 6|6@1+ (1,0) [0|63] ""  PC
 SG_ S2P_Bal_Type_27 : 12|2@1+ (1,0) [0|3] ""  PC
 SG_ S2P_Bal_TimeRemain_27 : 14|9@1+ (1,0) [0|511] ""  PC
 SG_ S2P_Bal_DeltaVolt_27 : 23|10@1+ (1,0) [0|1023] ""  PC
 SG_ S2P_Bal_CSCPowerCurr_27 : 33|11@1+ (1,0) [0|2047] ""  PC
 SG_ S2P_Bal_TypeLevel_27 : 44|3@1+ (1,0) [0|7] ""  PC
 SG_ S2P_Bal_SystemStatus_27 : 47|2@1+ (1,0) [0|3] ""  PC
 SG_ S2P_Bal_Strategy_27 : 49|1@1+ (1,0) [0|1] ""  PC
 SG_ S2P_Bal_ForceBalMode_27 : 50|2@1+ (1,0) [0|3] ""  PC
 SG_ S2P_Bal_CellTempFault_27 : 52|1@1+ (1,0) [0|1] ""  PC
 SG_ S2P_Bal_CellVoltFail_27 : 53|1@1+ (1,0) [0|1] ""  PC
 SG_ S2P_Bal_CloseBalInstruct_27 : 54|1@1+ (1,0) [0|1] ""  PC
 SG_ S2P_Bal_CCanTimeOut_27 : 55|1@1+ (1,0) [0|1] ""  PC
 SG_ S2P_Bal_CellOffLine_27 : 56|1@1+ (1,0) [0|1] ""  PC
 SG_ S2P_Bal_BalanceCircuitFault_27 : 57|1@1+ (1,0) [0|1] ""  PC
 SG_ S2P_Bal_CSCSourceVoltFault_27 : 58|1@1+ (1,0) [0|1] ""  PC
 SG_ S2P_Bal_CellVoltOverFault_27 : 59|1@1+ (1,0) [0|1] ""  PC
 SG_ S2P_Bal_CellVoltLowFault_27 : 60|1@1+ (1,0) [0|1] ""  PC
 SG_ S2P_Bal_CSCPCBTempFault_27 : 61|1@1+ (1,0) [0|1] ""  PC
 SG_ S2P_Bal_CSCSourceCurrLowFault_27 : 62|1@1+ (1,0) [0|1] ""  PC
 SG_ S2P_Bal_CSCSourceCurrOvrFault_27 : 63|1@1+ (1,0) [0|1] ""  PC

BO_ 2417487452 S2P_BL_Meg__28: 8 SBMU
 SG_ S2P_Bal_CSCNum_28 : 0|6@1+ (1,0) [0|63] ""  PC
 SG_ S2P_Bal_CellNum_28 : 6|6@1+ (1,0) [0|63] ""  PC
 SG_ S2P_Bal_Type_28 : 12|2@1+ (1,0) [0|3] ""  PC
 SG_ S2P_Bal_TimeRemain_28 : 14|9@1+ (1,0) [0|511] ""  PC
 SG_ S2P_Bal_DeltaVolt_28 : 23|10@1+ (1,0) [0|1023] ""  PC
 SG_ S2P_Bal_CSCPowerCurr_28 : 33|11@1+ (1,0) [0|2047] ""  PC
 SG_ S2P_Bal_TypeLevel_28 : 44|3@1+ (1,0) [0|7] ""  PC
 SG_ S2P_Bal_SystemStatus_28 : 47|2@1+ (1,0) [0|3] ""  PC
 SG_ S2P_Bal_Strategy_28 : 49|1@1+ (1,0) [0|1] ""  PC
 SG_ S2P_Bal_ForceBalMode_28 : 50|2@1+ (1,0) [0|3] ""  PC
 SG_ S2P_Bal_CellTempFault_28 : 52|1@1+ (1,0) [0|1] ""  PC
 SG_ S2P_Bal_CellVoltFail_28 : 53|1@1+ (1,0) [0|1] ""  PC
 SG_ S2P_Bal_CloseBalInstruct_28 : 54|1@1+ (1,0) [0|1] ""  PC
 SG_ S2P_Bal_CCanTimeOut_28 : 55|1@1+ (1,0) [0|1] ""  PC
 SG_ S2P_Bal_CellOffLine_28 : 56|1@1+ (1,0) [0|1] ""  PC
 SG_ S2P_Bal_BalanceCircuitFault_28 : 57|1@1+ (1,0) [0|1] ""  PC
 SG_ S2P_Bal_CSCSourceVoltFault_28 : 58|1@1+ (1,0) [0|1] ""  PC
 SG_ S2P_Bal_CellVoltOverFault_28 : 59|1@1+ (1,0) [0|1] ""  PC
 SG_ S2P_Bal_CellVoltLowFault_28 : 60|1@1+ (1,0) [0|1] ""  PC
 SG_ S2P_Bal_CSCPCBTempFault_28 : 61|1@1+ (1,0) [0|1] ""  PC
 SG_ S2P_Bal_CSCSourceCurrLowFault_28 : 62|1@1+ (1,0) [0|1] ""  PC
 SG_ S2P_Bal_CSCSourceCurrOvrFault_28 : 63|1@1+ (1,0) [0|1] ""  PC

BO_ 2417487453 S2P_BL_Meg__29: 8 SBMU
 SG_ S2P_Bal_CSCNum_29 : 0|6@1+ (1,0) [0|63] ""  PC
 SG_ S2P_Bal_CellNum_29 : 6|6@1+ (1,0) [0|63] ""  PC
 SG_ S2P_Bal_Type_29 : 12|2@1+ (1,0) [0|3] ""  PC
 SG_ S2P_Bal_TimeRemain_29 : 14|9@1+ (1,0) [0|511] ""  PC
 SG_ S2P_Bal_DeltaVolt_29 : 23|10@1+ (1,0) [0|1023] ""  PC
 SG_ S2P_Bal_CSCPowerCurr_29 : 33|11@1+ (1,0) [0|2047] ""  PC
 SG_ S2P_Bal_TypeLevel_29 : 44|3@1+ (1,0) [0|7] ""  PC
 SG_ S2P_Bal_SystemStatus_29 : 47|2@1+ (1,0) [0|3] ""  PC
 SG_ S2P_Bal_Strategy_29 : 49|1@1+ (1,0) [0|1] ""  PC
 SG_ S2P_Bal_ForceBalMode_29 : 50|2@1+ (1,0) [0|3] ""  PC
 SG_ S2P_Bal_CellTempFault_29 : 52|1@1+ (1,0) [0|1] ""  PC
 SG_ S2P_Bal_CellVoltFail_29 : 53|1@1+ (1,0) [0|1] ""  PC
 SG_ S2P_Bal_CloseBalInstruct_29 : 54|1@1+ (1,0) [0|1] ""  PC
 SG_ S2P_Bal_CCanTimeOut_29 : 55|1@1+ (1,0) [0|1] ""  PC
 SG_ S2P_Bal_CellOffLine_29 : 56|1@1+ (1,0) [0|1] ""  PC
 SG_ S2P_Bal_BalanceCircuitFault_29 : 57|1@1+ (1,0) [0|1] ""  PC
 SG_ S2P_Bal_CSCSourceVoltFault_29 : 58|1@1+ (1,0) [0|1] ""  PC
 SG_ S2P_Bal_CellVoltOverFault_29 : 59|1@1+ (1,0) [0|1] ""  PC
 SG_ S2P_Bal_CellVoltLowFault_29 : 60|1@1+ (1,0) [0|1] ""  PC
 SG_ S2P_Bal_CSCPCBTempFault_29 : 61|1@1+ (1,0) [0|1] ""  PC
 SG_ S2P_Bal_CSCSourceCurrLowFault_29 : 62|1@1+ (1,0) [0|1] ""  PC
 SG_ S2P_Bal_CSCSourceCurrOvrFault_29 : 63|1@1+ (1,0) [0|1] ""  PC

BO_ 2417487454 S2P_BL_Meg__30: 8 SBMU
 SG_ S2P_Bal_CSCNum_30 : 0|6@1+ (1,0) [0|63] ""  PC
 SG_ S2P_Bal_CellNum_30 : 6|6@1+ (1,0) [0|63] ""  PC
 SG_ S2P_Bal_Type_30 : 12|2@1+ (1,0) [0|3] ""  PC
 SG_ S2P_Bal_TimeRemain_30 : 14|9@1+ (1,0) [0|511] ""  PC
 SG_ S2P_Bal_DeltaVolt_30 : 23|10@1+ (1,0) [0|1023] ""  PC
 SG_ S2P_Bal_CSCPowerCurr_30 : 33|11@1+ (1,0) [0|2047] ""  PC
 SG_ S2P_Bal_TypeLevel_30 : 44|3@1+ (1,0) [0|7] ""  PC
 SG_ S2P_Bal_SystemStatus_30 : 47|2@1+ (1,0) [0|3] ""  PC
 SG_ S2P_Bal_Strategy_30 : 49|1@1+ (1,0) [0|1] ""  PC
 SG_ S2P_Bal_ForceBalMode_30 : 50|2@1+ (1,0) [0|3] ""  PC
 SG_ S2P_Bal_CellTempFault_30 : 52|1@1+ (1,0) [0|1] ""  PC
 SG_ S2P_Bal_CellVoltFail_30 : 53|1@1+ (1,0) [0|1] ""  PC
 SG_ S2P_Bal_CloseBalInstruct_30 : 54|1@1+ (1,0) [0|1] ""  PC
 SG_ S2P_Bal_CCanTimeOut_30 : 55|1@1+ (1,0) [0|1] ""  PC
 SG_ S2P_Bal_CellOffLine_30 : 56|1@1+ (1,0) [0|1] ""  PC
 SG_ S2P_Bal_BalanceCircuitFault_30 : 57|1@1+ (1,0) [0|1] ""  PC
 SG_ S2P_Bal_CSCSourceVoltFault_30 : 58|1@1+ (1,0) [0|1] ""  PC
 SG_ S2P_Bal_CellVoltOverFault_30 : 59|1@1+ (1,0) [0|1] ""  PC
 SG_ S2P_Bal_CellVoltLowFault_30 : 60|1@1+ (1,0) [0|1] ""  PC
 SG_ S2P_Bal_CSCPCBTempFault_30 : 61|1@1+ (1,0) [0|1] ""  PC
 SG_ S2P_Bal_CSCSourceCurrLowFault_30 : 62|1@1+ (1,0) [0|1] ""  PC
 SG_ S2P_Bal_CSCSourceCurrOvrFault_30 : 63|1@1+ (1,0) [0|1] ""  PC

BO_ 2417487455 S2P_BL_Meg__31: 8 SBMU
 SG_ S2P_Bal_CSCNum_31 : 0|6@1+ (1,0) [0|63] ""  PC
 SG_ S2P_Bal_CellNum_31 : 6|6@1+ (1,0) [0|63] ""  PC
 SG_ S2P_Bal_Type_31 : 12|2@1+ (1,0) [0|3] ""  PC
 SG_ S2P_Bal_TimeRemain_31 : 14|9@1+ (1,0) [0|511] ""  PC
 SG_ S2P_Bal_DeltaVolt_31 : 23|10@1+ (1,0) [0|1023] ""  PC
 SG_ S2P_Bal_CSCPowerCurr_31 : 33|11@1+ (1,0) [0|2047] ""  PC
 SG_ S2P_Bal_TypeLevel_31 : 44|3@1+ (1,0) [0|7] ""  PC
 SG_ S2P_Bal_SystemStatus_31 : 47|2@1+ (1,0) [0|3] ""  PC
 SG_ S2P_Bal_Strategy_31 : 49|1@1+ (1,0) [0|1] ""  PC
 SG_ S2P_Bal_ForceBalMode_31 : 50|2@1+ (1,0) [0|3] ""  PC
 SG_ S2P_Bal_CellTempFault_31 : 52|1@1+ (1,0) [0|1] ""  PC
 SG_ S2P_Bal_CellVoltFail_31 : 53|1@1+ (1,0) [0|1] ""  PC
 SG_ S2P_Bal_CloseBalInstruct_31 : 54|1@1+ (1,0) [0|1] ""  PC
 SG_ S2P_Bal_CCanTimeOut_31 : 55|1@1+ (1,0) [0|1] ""  PC
 SG_ S2P_Bal_CellOffLine_31 : 56|1@1+ (1,0) [0|1] ""  PC
 SG_ S2P_Bal_BalanceCircuitFault_31 : 57|1@1+ (1,0) [0|1] ""  PC
 SG_ S2P_Bal_CSCSourceVoltFault_31 : 58|1@1+ (1,0) [0|1] ""  PC
 SG_ S2P_Bal_CellVoltOverFault_31 : 59|1@1+ (1,0) [0|1] ""  PC
 SG_ S2P_Bal_CellVoltLowFault_31 : 60|1@1+ (1,0) [0|1] ""  PC
 SG_ S2P_Bal_CSCPCBTempFault_31 : 61|1@1+ (1,0) [0|1] ""  PC
 SG_ S2P_Bal_CSCSourceCurrLowFault_31 : 62|1@1+ (1,0) [0|1] ""  PC
 SG_ S2P_Bal_CSCSourceCurrOvrFault_31 : 63|1@1+ (1,0) [0|1] ""  PC

BO_ 2417487456 S2P_BL_Meg__32: 8 SBMU
 SG_ S2P_Bal_CSCNum_32 : 0|6@1+ (1,0) [0|63] ""  PC
 SG_ S2P_Bal_CellNum_32 : 6|6@1+ (1,0) [0|63] ""  PC
 SG_ S2P_Bal_Type_32 : 12|2@1+ (1,0) [0|3] ""  PC
 SG_ S2P_Bal_TimeRemain_32 : 14|9@1+ (1,0) [0|511] ""  PC
 SG_ S2P_Bal_DeltaVolt_32 : 23|10@1+ (1,0) [0|1023] ""  PC
 SG_ S2P_Bal_CSCPowerCurr_32 : 33|11@1+ (1,0) [0|2047] ""  PC
 SG_ S2P_Bal_TypeLevel_32 : 44|3@1+ (1,0) [0|7] ""  PC
 SG_ S2P_Bal_SystemStatus_32 : 47|2@1+ (1,0) [0|3] ""  PC
 SG_ S2P_Bal_Strategy_32 : 49|1@1+ (1,0) [0|1] ""  PC
 SG_ S2P_Bal_ForceBalMode_32 : 50|2@1+ (1,0) [0|3] ""  PC
 SG_ S2P_Bal_CellTempFault_32 : 52|1@1+ (1,0) [0|1] ""  PC
 SG_ S2P_Bal_CellVoltFail_32 : 53|1@1+ (1,0) [0|1] ""  PC
 SG_ S2P_Bal_CloseBalInstruct_32 : 54|1@1+ (1,0) [0|1] ""  PC
 SG_ S2P_Bal_CCanTimeOut_32 : 55|1@1+ (1,0) [0|1] ""  PC
 SG_ S2P_Bal_CellOffLine_32 : 56|1@1+ (1,0) [0|1] ""  PC
 SG_ S2P_Bal_BalanceCircuitFault_32 : 57|1@1+ (1,0) [0|1] ""  PC
 SG_ S2P_Bal_CSCSourceVoltFault_32 : 58|1@1+ (1,0) [0|1] ""  PC
 SG_ S2P_Bal_CellVoltOverFault_32 : 59|1@1+ (1,0) [0|1] ""  PC
 SG_ S2P_Bal_CellVoltLowFault_32 : 60|1@1+ (1,0) [0|1] ""  PC
 SG_ S2P_Bal_CSCPCBTempFault_32 : 61|1@1+ (1,0) [0|1] ""  PC
 SG_ S2P_Bal_CSCSourceCurrLowFault_32 : 62|1@1+ (1,0) [0|1] ""  PC
 SG_ S2P_Bal_CSCSourceCurrOvrFault_32 : 63|1@1+ (1,0) [0|1] ""  PC

BO_ 2417487457 S2P_BL_Meg__33: 8 SBMU
 SG_ S2P_Bal_CSCNum_33 : 0|6@1+ (1,0) [0|63] ""  PC
 SG_ S2P_Bal_CellNum_33 : 6|6@1+ (1,0) [0|63] ""  PC
 SG_ S2P_Bal_Type_33 : 12|2@1+ (1,0) [0|3] ""  PC
 SG_ S2P_Bal_TimeRemain_33 : 14|9@1+ (1,0) [0|511] ""  PC
 SG_ S2P_Bal_DeltaVolt_33 : 23|10@1+ (1,0) [0|1023] ""  PC
 SG_ S2P_Bal_CSCPowerCurr_33 : 33|11@1+ (1,0) [0|2047] ""  PC
 SG_ S2P_Bal_TypeLevel_33 : 44|3@1+ (1,0) [0|7] ""  PC
 SG_ S2P_Bal_SystemStatus_33 : 47|2@1+ (1,0) [0|3] ""  PC
 SG_ S2P_Bal_Strategy_33 : 49|1@1+ (1,0) [0|1] ""  PC
 SG_ S2P_Bal_ForceBalMode_33 : 50|2@1+ (1,0) [0|3] ""  PC
 SG_ S2P_Bal_CellTempFault_33 : 52|1@1+ (1,0) [0|1] ""  PC
 SG_ S2P_Bal_CellVoltFail_33 : 53|1@1+ (1,0) [0|1] ""  PC
 SG_ S2P_Bal_CloseBalInstruct_33 : 54|1@1+ (1,0) [0|1] ""  PC
 SG_ S2P_Bal_CCanTimeOut_33 : 55|1@1+ (1,0) [0|1] ""  PC
 SG_ S2P_Bal_CellOffLine_33 : 56|1@1+ (1,0) [0|1] ""  PC
 SG_ S2P_Bal_BalanceCircuitFault_33 : 57|1@1+ (1,0) [0|1] ""  PC
 SG_ S2P_Bal_CSCSourceVoltFault_33 : 58|1@1+ (1,0) [0|1] ""  PC
 SG_ S2P_Bal_CellVoltOverFault_33 : 59|1@1+ (1,0) [0|1] ""  PC
 SG_ S2P_Bal_CellVoltLowFault_33 : 60|1@1+ (1,0) [0|1] ""  PC
 SG_ S2P_Bal_CSCPCBTempFault_33 : 61|1@1+ (1,0) [0|1] ""  PC
 SG_ S2P_Bal_CSCSourceCurrLowFault_33 : 62|1@1+ (1,0) [0|1] ""  PC
 SG_ S2P_Bal_CSCSourceCurrOvrFault_33 : 63|1@1+ (1,0) [0|1] ""  PC

BO_ 2417487458 S2P_BL_Meg__34: 8 SBMU
 SG_ S2P_Bal_CSCNum_34 : 0|6@1+ (1,0) [0|63] ""  PC
 SG_ S2P_Bal_CellNum_34 : 6|6@1+ (1,0) [0|63] ""  PC
 SG_ S2P_Bal_Type_34 : 12|2@1+ (1,0) [0|3] ""  PC
 SG_ S2P_Bal_TimeRemain_34 : 14|9@1+ (1,0) [0|511] ""  PC
 SG_ S2P_Bal_DeltaVolt_34 : 23|10@1+ (1,0) [0|1023] ""  PC
 SG_ S2P_Bal_CSCPowerCurr_34 : 33|11@1+ (1,0) [0|2047] ""  PC
 SG_ S2P_Bal_TypeLevel_34 : 44|3@1+ (1,0) [0|7] ""  PC
 SG_ S2P_Bal_SystemStatus_34 : 47|2@1+ (1,0) [0|3] ""  PC
 SG_ S2P_Bal_Strategy_34 : 49|1@1+ (1,0) [0|1] ""  PC
 SG_ S2P_Bal_ForceBalMode_34 : 50|2@1+ (1,0) [0|3] ""  PC
 SG_ S2P_Bal_CellTempFault_34 : 52|1@1+ (1,0) [0|1] ""  PC
 SG_ S2P_Bal_CellVoltFail_34 : 53|1@1+ (1,0) [0|1] ""  PC
 SG_ S2P_Bal_CloseBalInstruct_34 : 54|1@1+ (1,0) [0|1] ""  PC
 SG_ S2P_Bal_CCanTimeOut_34 : 55|1@1+ (1,0) [0|1] ""  PC
 SG_ S2P_Bal_CellOffLine_34 : 56|1@1+ (1,0) [0|1] ""  PC
 SG_ S2P_Bal_BalanceCircuitFault_34 : 57|1@1+ (1,0) [0|1] ""  PC
 SG_ S2P_Bal_CSCSourceVoltFault_34 : 58|1@1+ (1,0) [0|1] ""  PC
 SG_ S2P_Bal_CellVoltOverFault_34 : 59|1@1+ (1,0) [0|1] ""  PC
 SG_ S2P_Bal_CellVoltLowFault_34 : 60|1@1+ (1,0) [0|1] ""  PC
 SG_ S2P_Bal_CSCPCBTempFault_34 : 61|1@1+ (1,0) [0|1] ""  PC
 SG_ S2P_Bal_CSCSourceCurrLowFault_34 : 62|1@1+ (1,0) [0|1] ""  PC
 SG_ S2P_Bal_CSCSourceCurrOvrFault_34 : 63|1@1+ (1,0) [0|1] ""  PC

BO_ 2417487459 S2P_BL_Meg__35: 8 SBMU
 SG_ S2P_Bal_CSCNum_35 : 0|6@1+ (1,0) [0|63] ""  PC
 SG_ S2P_Bal_CellNum_35 : 6|6@1+ (1,0) [0|63] ""  PC
 SG_ S2P_Bal_Type_35 : 12|2@1+ (1,0) [0|3] ""  PC
 SG_ S2P_Bal_TimeRemain_35 : 14|9@1+ (1,0) [0|511] ""  PC
 SG_ S2P_Bal_DeltaVolt_35 : 23|10@1+ (1,0) [0|1023] ""  PC
 SG_ S2P_Bal_CSCPowerCurr_35 : 33|11@1+ (1,0) [0|2047] ""  PC
 SG_ S2P_Bal_TypeLevel_35 : 44|3@1+ (1,0) [0|7] ""  PC
 SG_ S2P_Bal_SystemStatus_35 : 47|2@1+ (1,0) [0|3] ""  PC
 SG_ S2P_Bal_Strategy_35 : 49|1@1+ (1,0) [0|1] ""  PC
 SG_ S2P_Bal_ForceBalMode_35 : 50|2@1+ (1,0) [0|3] ""  PC
 SG_ S2P_Bal_CellTempFault_35 : 52|1@1+ (1,0) [0|1] ""  PC
 SG_ S2P_Bal_CellVoltFail_35 : 53|1@1+ (1,0) [0|1] ""  PC
 SG_ S2P_Bal_CloseBalInstruct_35 : 54|1@1+ (1,0) [0|1] ""  PC
 SG_ S2P_Bal_CCanTimeOut_35 : 55|1@1+ (1,0) [0|1] ""  PC
 SG_ S2P_Bal_CellOffLine_35 : 56|1@1+ (1,0) [0|1] ""  PC
 SG_ S2P_Bal_BalanceCircuitFault_35 : 57|1@1+ (1,0) [0|1] ""  PC
 SG_ S2P_Bal_CSCSourceVoltFault_35 : 58|1@1+ (1,0) [0|1] ""  PC
 SG_ S2P_Bal_CellVoltOverFault_35 : 59|1@1+ (1,0) [0|1] ""  PC
 SG_ S2P_Bal_CellVoltLowFault_35 : 60|1@1+ (1,0) [0|1] ""  PC
 SG_ S2P_Bal_CSCPCBTempFault_35 : 61|1@1+ (1,0) [0|1] ""  PC
 SG_ S2P_Bal_CSCSourceCurrLowFault_35 : 62|1@1+ (1,0) [0|1] ""  PC
 SG_ S2P_Bal_CSCSourceCurrOvrFault_35 : 63|1@1+ (1,0) [0|1] ""  PC

BO_ 2417487460 S2P_BL_Meg__36: 8 SBMU
 SG_ S2P_Bal_CSCNum_36 : 0|6@1+ (1,0) [0|63] ""  PC
 SG_ S2P_Bal_CellNum_36 : 6|6@1+ (1,0) [0|63] ""  PC
 SG_ S2P_Bal_Type_36 : 12|2@1+ (1,0) [0|3] ""  PC
 SG_ S2P_Bal_TimeRemain_36 : 14|9@1+ (1,0) [0|511] ""  PC
 SG_ S2P_Bal_DeltaVolt_36 : 23|10@1+ (1,0) [0|1023] ""  PC
 SG_ S2P_Bal_CSCPowerCurr_36 : 33|11@1+ (1,0) [0|2047] ""  PC
 SG_ S2P_Bal_TypeLevel_36 : 44|3@1+ (1,0) [0|7] ""  PC
 SG_ S2P_Bal_SystemStatus_36 : 47|2@1+ (1,0) [0|3] ""  PC
 SG_ S2P_Bal_Strategy_36 : 49|1@1+ (1,0) [0|1] ""  PC
 SG_ S2P_Bal_ForceBalMode_36 : 50|2@1+ (1,0) [0|3] ""  PC
 SG_ S2P_Bal_CellTempFault_36 : 52|1@1+ (1,0) [0|1] ""  PC
 SG_ S2P_Bal_CellVoltFail_36 : 53|1@1+ (1,0) [0|1] ""  PC
 SG_ S2P_Bal_CloseBalInstruct_36 : 54|1@1+ (1,0) [0|1] ""  PC
 SG_ S2P_Bal_CCanTimeOut_36 : 55|1@1+ (1,0) [0|1] ""  PC
 SG_ S2P_Bal_CellOffLine_36 : 56|1@1+ (1,0) [0|1] ""  PC
 SG_ S2P_Bal_BalanceCircuitFault_36 : 57|1@1+ (1,0) [0|1] ""  PC
 SG_ S2P_Bal_CSCSourceVoltFault_36 : 58|1@1+ (1,0) [0|1] ""  PC
 SG_ S2P_Bal_CellVoltOverFault_36 : 59|1@1+ (1,0) [0|1] ""  PC
 SG_ S2P_Bal_CellVoltLowFault_36 : 60|1@1+ (1,0) [0|1] ""  PC
 SG_ S2P_Bal_CSCPCBTempFault_36 : 61|1@1+ (1,0) [0|1] ""  PC
 SG_ S2P_Bal_CSCSourceCurrLowFault_36 : 62|1@1+ (1,0) [0|1] ""  PC
 SG_ S2P_Bal_CSCSourceCurrOvrFault_36 : 63|1@1+ (1,0) [0|1] ""  PC

BO_ 2417487461 S2P_BL_Meg__37: 8 SBMU
 SG_ S2P_Bal_CSCNum_37 : 0|6@1+ (1,0) [0|63] ""  PC
 SG_ S2P_Bal_CellNum_37 : 6|6@1+ (1,0) [0|63] ""  PC
 SG_ S2P_Bal_Type_37 : 12|2@1+ (1,0) [0|3] ""  PC
 SG_ S2P_Bal_TimeRemain_37 : 14|9@1+ (1,0) [0|511] ""  PC
 SG_ S2P_Bal_DeltaVolt_37 : 23|10@1+ (1,0) [0|1023] ""  PC
 SG_ S2P_Bal_CSCPowerCurr_37 : 33|11@1+ (1,0) [0|2047] ""  PC
 SG_ S2P_Bal_TypeLevel_37 : 44|3@1+ (1,0) [0|7] ""  PC
 SG_ S2P_Bal_SystemStatus_37 : 47|2@1+ (1,0) [0|3] ""  PC
 SG_ S2P_Bal_Strategy_37 : 49|1@1+ (1,0) [0|1] ""  PC
 SG_ S2P_Bal_ForceBalMode_37 : 50|2@1+ (1,0) [0|3] ""  PC
 SG_ S2P_Bal_CellTempFault_37 : 52|1@1+ (1,0) [0|1] ""  PC
 SG_ S2P_Bal_CellVoltFail_37 : 53|1@1+ (1,0) [0|1] ""  PC
 SG_ S2P_Bal_CloseBalInstruct_37 : 54|1@1+ (1,0) [0|1] ""  PC
 SG_ S2P_Bal_CCanTimeOut_37 : 55|1@1+ (1,0) [0|1] ""  PC
 SG_ S2P_Bal_CellOffLine_37 : 56|1@1+ (1,0) [0|1] ""  PC
 SG_ S2P_Bal_BalanceCircuitFault_37 : 57|1@1+ (1,0) [0|1] ""  PC
 SG_ S2P_Bal_CSCSourceVoltFault_37 : 58|1@1+ (1,0) [0|1] ""  PC
 SG_ S2P_Bal_CellVoltOverFault_37 : 59|1@1+ (1,0) [0|1] ""  PC
 SG_ S2P_Bal_CellVoltLowFault_37 : 60|1@1+ (1,0) [0|1] ""  PC
 SG_ S2P_Bal_CSCPCBTempFault_37 : 61|1@1+ (1,0) [0|1] ""  PC
 SG_ S2P_Bal_CSCSourceCurrLowFault_37 : 62|1@1+ (1,0) [0|1] ""  PC
 SG_ S2P_Bal_CSCSourceCurrOvrFault_37 : 63|1@1+ (1,0) [0|1] ""  PC

BO_ 2417487462 S2P_BL_Meg__38: 8 SBMU
 SG_ S2P_Bal_CSCNum_38 : 0|6@1+ (1,0) [0|63] ""  PC
 SG_ S2P_Bal_CellNum_38 : 6|6@1+ (1,0) [0|63] ""  PC
 SG_ S2P_Bal_Type_38 : 12|2@1+ (1,0) [0|3] ""  PC
 SG_ S2P_Bal_TimeRemain_38 : 14|9@1+ (1,0) [0|511] ""  PC
 SG_ S2P_Bal_DeltaVolt_38 : 23|10@1+ (1,0) [0|1023] ""  PC
 SG_ S2P_Bal_CSCPowerCurr_38 : 33|11@1+ (1,0) [0|2047] ""  PC
 SG_ S2P_Bal_TypeLevel_38 : 44|3@1+ (1,0) [0|7] ""  PC
 SG_ S2P_Bal_SystemStatus_38 : 47|2@1+ (1,0) [0|3] ""  PC
 SG_ S2P_Bal_Strategy_38 : 49|1@1+ (1,0) [0|1] ""  PC
 SG_ S2P_Bal_ForceBalMode_38 : 50|2@1+ (1,0) [0|3] ""  PC
 SG_ S2P_Bal_CellTempFault_38 : 52|1@1+ (1,0) [0|1] ""  PC
 SG_ S2P_Bal_CellVoltFail_38 : 53|1@1+ (1,0) [0|1] ""  PC
 SG_ S2P_Bal_CloseBalInstruct_38 : 54|1@1+ (1,0) [0|1] ""  PC
 SG_ S2P_Bal_CCanTimeOut_38 : 55|1@1+ (1,0) [0|1] ""  PC
 SG_ S2P_Bal_CellOffLine_38 : 56|1@1+ (1,0) [0|1] ""  PC
 SG_ S2P_Bal_BalanceCircuitFault_38 : 57|1@1+ (1,0) [0|1] ""  PC
 SG_ S2P_Bal_CSCSourceVoltFault_38 : 58|1@1+ (1,0) [0|1] ""  PC
 SG_ S2P_Bal_CellVoltOverFault_38 : 59|1@1+ (1,0) [0|1] ""  PC
 SG_ S2P_Bal_CellVoltLowFault_38 : 60|1@1+ (1,0) [0|1] ""  PC
 SG_ S2P_Bal_CSCPCBTempFault_38 : 61|1@1+ (1,0) [0|1] ""  PC
 SG_ S2P_Bal_CSCSourceCurrLowFault_38 : 62|1@1+ (1,0) [0|1] ""  PC
 SG_ S2P_Bal_CSCSourceCurrOvrFault_38 : 63|1@1+ (1,0) [0|1] ""  PC

BO_ 2417487463 S2P_BL_Meg__39: 8 SBMU
 SG_ S2P_Bal_CSCNum_39 : 0|6@1+ (1,0) [0|63] ""  PC
 SG_ S2P_Bal_CellNum_39 : 6|6@1+ (1,0) [0|63] ""  PC
 SG_ S2P_Bal_Type_39 : 12|2@1+ (1,0) [0|3] ""  PC
 SG_ S2P_Bal_TimeRemain_39 : 14|9@1+ (1,0) [0|511] ""  PC
 SG_ S2P_Bal_DeltaVolt_39 : 23|10@1+ (1,0) [0|1023] ""  PC
 SG_ S2P_Bal_CSCPowerCurr_39 : 33|11@1+ (1,0) [0|2047] ""  PC
 SG_ S2P_Bal_TypeLevel_39 : 44|3@1+ (1,0) [0|7] ""  PC
 SG_ S2P_Bal_SystemStatus_39 : 47|2@1+ (1,0) [0|3] ""  PC
 SG_ S2P_Bal_Strategy_39 : 49|1@1+ (1,0) [0|1] ""  PC
 SG_ S2P_Bal_ForceBalMode_39 : 50|2@1+ (1,0) [0|3] ""  PC
 SG_ S2P_Bal_CellTempFault_39 : 52|1@1+ (1,0) [0|1] ""  PC
 SG_ S2P_Bal_CellVoltFail_39 : 53|1@1+ (1,0) [0|1] ""  PC
 SG_ S2P_Bal_CloseBalInstruct_39 : 54|1@1+ (1,0) [0|1] ""  PC
 SG_ S2P_Bal_CCanTimeOut_39 : 55|1@1+ (1,0) [0|1] ""  PC
 SG_ S2P_Bal_CellOffLine_39 : 56|1@1+ (1,0) [0|1] ""  PC
 SG_ S2P_Bal_BalanceCircuitFault_39 : 57|1@1+ (1,0) [0|1] ""  PC
 SG_ S2P_Bal_CSCSourceVoltFault_39 : 58|1@1+ (1,0) [0|1] ""  PC
 SG_ S2P_Bal_CellVoltOverFault_39 : 59|1@1+ (1,0) [0|1] ""  PC
 SG_ S2P_Bal_CellVoltLowFault_39 : 60|1@1+ (1,0) [0|1] ""  PC
 SG_ S2P_Bal_CSCPCBTempFault_39 : 61|1@1+ (1,0) [0|1] ""  PC
 SG_ S2P_Bal_CSCSourceCurrLowFault_39 : 62|1@1+ (1,0) [0|1] ""  PC
 SG_ S2P_Bal_CSCSourceCurrOvrFault_39 : 63|1@1+ (1,0) [0|1] ""  PC

BO_ 2417487464 S2P_BL_Meg__40: 8 SBMU
 SG_ S2P_Bal_CSCNum_40 : 0|6@1+ (1,0) [0|63] ""  PC
 SG_ S2P_Bal_CellNum_40 : 6|6@1+ (1,0) [0|63] ""  PC
 SG_ S2P_Bal_Type_40 : 12|2@1+ (1,0) [0|3] ""  PC
 SG_ S2P_Bal_TimeRemain_40 : 14|9@1+ (1,0) [0|511] ""  PC
 SG_ S2P_Bal_DeltaVolt_40 : 23|10@1+ (1,0) [0|1023] ""  PC
 SG_ S2P_Bal_CSCPowerCurr_40 : 33|11@1+ (1,0) [0|2047] ""  PC
 SG_ S2P_Bal_TypeLevel_40 : 44|3@1+ (1,0) [0|7] ""  PC
 SG_ S2P_Bal_SystemStatus_40 : 47|2@1+ (1,0) [0|3] ""  PC
 SG_ S2P_Bal_Strategy_40 : 49|1@1+ (1,0) [0|1] ""  PC
 SG_ S2P_Bal_ForceBalMode_40 : 50|2@1+ (1,0) [0|3] ""  PC
 SG_ S2P_Bal_CellTempFault_40 : 52|1@1+ (1,0) [0|1] ""  PC
 SG_ S2P_Bal_CellVoltFail_40 : 53|1@1+ (1,0) [0|1] ""  PC
 SG_ S2P_Bal_CloseBalInstruct_40 : 54|1@1+ (1,0) [0|1] ""  PC
 SG_ S2P_Bal_CCanTimeOut_40 : 55|1@1+ (1,0) [0|1] ""  PC
 SG_ S2P_Bal_CellOffLine_40 : 56|1@1+ (1,0) [0|1] ""  PC
 SG_ S2P_Bal_BalanceCircuitFault_40 : 57|1@1+ (1,0) [0|1] ""  PC
 SG_ S2P_Bal_CSCSourceVoltFault_40 : 58|1@1+ (1,0) [0|1] ""  PC
 SG_ S2P_Bal_CellVoltOverFault_40 : 59|1@1+ (1,0) [0|1] ""  PC
 SG_ S2P_Bal_CellVoltLowFault_40 : 60|1@1+ (1,0) [0|1] ""  PC
 SG_ S2P_Bal_CSCPCBTempFault_40 : 61|1@1+ (1,0) [0|1] ""  PC
 SG_ S2P_Bal_CSCSourceCurrLowFault_40 : 62|1@1+ (1,0) [0|1] ""  PC
 SG_ S2P_Bal_CSCSourceCurrOvrFault_40 : 63|1@1+ (1,0) [0|1] ""  PC

BO_ 2417487465 S2P_BL_Meg__41: 8 SBMU
 SG_ S2P_Bal_CSCNum_41 : 0|6@1+ (1,0) [0|63] ""  PC
 SG_ S2P_Bal_CellNum_41 : 6|6@1+ (1,0) [0|63] ""  PC
 SG_ S2P_Bal_Type_41 : 12|2@1+ (1,0) [0|3] ""  PC
 SG_ S2P_Bal_TimeRemain_41 : 14|9@1+ (1,0) [0|511] ""  PC
 SG_ S2P_Bal_DeltaVolt_41 : 23|10@1+ (1,0) [0|1023] ""  PC
 SG_ S2P_Bal_CSCPowerCurr_41 : 33|11@1+ (1,0) [0|2047] ""  PC
 SG_ S2P_Bal_TypeLevel_41 : 44|3@1+ (1,0) [0|7] ""  PC
 SG_ S2P_Bal_SystemStatus_41 : 47|2@1+ (1,0) [0|3] ""  PC
 SG_ S2P_Bal_Strategy_41 : 49|1@1+ (1,0) [0|1] ""  PC
 SG_ S2P_Bal_ForceBalMode_41 : 50|2@1+ (1,0) [0|3] ""  PC
 SG_ S2P_Bal_CellTempFault_41 : 52|1@1+ (1,0) [0|1] ""  PC
 SG_ S2P_Bal_CellVoltFail_41 : 53|1@1+ (1,0) [0|1] ""  PC
 SG_ S2P_Bal_CloseBalInstruct_41 : 54|1@1+ (1,0) [0|1] ""  PC
 SG_ S2P_Bal_CCanTimeOut_41 : 55|1@1+ (1,0) [0|1] ""  PC
 SG_ S2P_Bal_CellOffLine_41 : 56|1@1+ (1,0) [0|1] ""  PC
 SG_ S2P_Bal_BalanceCircuitFault_41 : 57|1@1+ (1,0) [0|1] ""  PC
 SG_ S2P_Bal_CSCSourceVoltFault_41 : 58|1@1+ (1,0) [0|1] ""  PC
 SG_ S2P_Bal_CellVoltOverFault_41 : 59|1@1+ (1,0) [0|1] ""  PC
 SG_ S2P_Bal_CellVoltLowFault_41 : 60|1@1+ (1,0) [0|1] ""  PC
 SG_ S2P_Bal_CSCPCBTempFault_41 : 61|1@1+ (1,0) [0|1] ""  PC
 SG_ S2P_Bal_CSCSourceCurrLowFault_41 : 62|1@1+ (1,0) [0|1] ""  PC
 SG_ S2P_Bal_CSCSourceCurrOvrFault_41 : 63|1@1+ (1,0) [0|1] ""  PC

BO_ 2417487466 S2P_BL_Meg__42: 8 SBMU
 SG_ S2P_Bal_CSCNum_42 : 0|6@1+ (1,0) [0|63] ""  PC
 SG_ S2P_Bal_CellNum_42 : 6|6@1+ (1,0) [0|63] ""  PC
 SG_ S2P_Bal_Type_42 : 12|2@1+ (1,0) [0|3] ""  PC
 SG_ S2P_Bal_TimeRemain_42 : 14|9@1+ (1,0) [0|511] ""  PC
 SG_ S2P_Bal_DeltaVolt_42 : 23|10@1+ (1,0) [0|1023] ""  PC
 SG_ S2P_Bal_CSCPowerCurr_42 : 33|11@1+ (1,0) [0|2047] ""  PC
 SG_ S2P_Bal_TypeLevel_42 : 44|3@1+ (1,0) [0|7] ""  PC
 SG_ S2P_Bal_SystemStatus_42 : 47|2@1+ (1,0) [0|3] ""  PC
 SG_ S2P_Bal_Strategy_42 : 49|1@1+ (1,0) [0|1] ""  PC
 SG_ S2P_Bal_ForceBalMode_42 : 50|2@1+ (1,0) [0|3] ""  PC
 SG_ S2P_Bal_CellTempFault_42 : 52|1@1+ (1,0) [0|1] ""  PC
 SG_ S2P_Bal_CellVoltFail_42 : 53|1@1+ (1,0) [0|1] ""  PC
 SG_ S2P_Bal_CloseBalInstruct_42 : 54|1@1+ (1,0) [0|1] ""  PC
 SG_ S2P_Bal_CCanTimeOut_42 : 55|1@1+ (1,0) [0|1] ""  PC
 SG_ S2P_Bal_CellOffLine_42 : 56|1@1+ (1,0) [0|1] ""  PC
 SG_ S2P_Bal_BalanceCircuitFault_42 : 57|1@1+ (1,0) [0|1] ""  PC
 SG_ S2P_Bal_CSCSourceVoltFault_42 : 58|1@1+ (1,0) [0|1] ""  PC
 SG_ S2P_Bal_CellVoltOverFault_42 : 59|1@1+ (1,0) [0|1] ""  PC
 SG_ S2P_Bal_CellVoltLowFault_42 : 60|1@1+ (1,0) [0|1] ""  PC
 SG_ S2P_Bal_CSCPCBTempFault_42 : 61|1@1+ (1,0) [0|1] ""  PC
 SG_ S2P_Bal_CSCSourceCurrLowFault_42 : 62|1@1+ (1,0) [0|1] ""  PC
 SG_ S2P_Bal_CSCSourceCurrOvrFault_42 : 63|1@1+ (1,0) [0|1] ""  PC

BO_ 2417487467 S2P_BL_Meg__43: 8 SBMU
 SG_ S2P_Bal_CSCNum_43 : 0|6@1+ (1,0) [0|63] ""  PC
 SG_ S2P_Bal_CellNum_43 : 6|6@1+ (1,0) [0|63] ""  PC
 SG_ S2P_Bal_Type_43 : 12|2@1+ (1,0) [0|3] ""  PC
 SG_ S2P_Bal_TimeRemain_43 : 14|9@1+ (1,0) [0|511] ""  PC
 SG_ S2P_Bal_DeltaVolt_43 : 23|10@1+ (1,0) [0|1023] ""  PC
 SG_ S2P_Bal_CSCPowerCurr_43 : 33|11@1+ (1,0) [0|2047] ""  PC
 SG_ S2P_Bal_TypeLevel_43 : 44|3@1+ (1,0) [0|7] ""  PC
 SG_ S2P_Bal_SystemStatus_43 : 47|2@1+ (1,0) [0|3] ""  PC
 SG_ S2P_Bal_Strategy_43 : 49|1@1+ (1,0) [0|1] ""  PC
 SG_ S2P_Bal_ForceBalMode_43 : 50|2@1+ (1,0) [0|3] ""  PC
 SG_ S2P_Bal_CellTempFault_43 : 52|1@1+ (1,0) [0|1] ""  PC
 SG_ S2P_Bal_CellVoltFail_43 : 53|1@1+ (1,0) [0|1] ""  PC
 SG_ S2P_Bal_CloseBalInstruct_43 : 54|1@1+ (1,0) [0|1] ""  PC
 SG_ S2P_Bal_CCanTimeOut_43 : 55|1@1+ (1,0) [0|1] ""  PC
 SG_ S2P_Bal_CellOffLine_43 : 56|1@1+ (1,0) [0|1] ""  PC
 SG_ S2P_Bal_BalanceCircuitFault_43 : 57|1@1+ (1,0) [0|1] ""  PC
 SG_ S2P_Bal_CSCSourceVoltFault_43 : 58|1@1+ (1,0) [0|1] ""  PC
 SG_ S2P_Bal_CellVoltOverFault_43 : 59|1@1+ (1,0) [0|1] ""  PC
 SG_ S2P_Bal_CellVoltLowFault_43 : 60|1@1+ (1,0) [0|1] ""  PC
 SG_ S2P_Bal_CSCPCBTempFault_43 : 61|1@1+ (1,0) [0|1] ""  PC
 SG_ S2P_Bal_CSCSourceCurrLowFault_43 : 62|1@1+ (1,0) [0|1] ""  PC
 SG_ S2P_Bal_CSCSourceCurrOvrFault_43 : 63|1@1+ (1,0) [0|1] ""  PC

BO_ 2417487468 S2P_BL_Meg__44: 8 SBMU
 SG_ S2P_Bal_CSCNum_44 : 0|6@1+ (1,0) [0|63] ""  PC
 SG_ S2P_Bal_CellNum_44 : 6|6@1+ (1,0) [0|63] ""  PC
 SG_ S2P_Bal_Type_44 : 12|2@1+ (1,0) [0|3] ""  PC
 SG_ S2P_Bal_TimeRemain_44 : 14|9@1+ (1,0) [0|511] ""  PC
 SG_ S2P_Bal_DeltaVolt_44 : 23|10@1+ (1,0) [0|1023] ""  PC
 SG_ S2P_Bal_CSCPowerCurr_44 : 33|11@1+ (1,0) [0|2047] ""  PC
 SG_ S2P_Bal_TypeLevel_44 : 44|3@1+ (1,0) [0|7] ""  PC
 SG_ S2P_Bal_SystemStatus_44 : 47|2@1+ (1,0) [0|3] ""  PC
 SG_ S2P_Bal_Strategy_44 : 49|1@1+ (1,0) [0|1] ""  PC
 SG_ S2P_Bal_ForceBalMode_44 : 50|2@1+ (1,0) [0|3] ""  PC
 SG_ S2P_Bal_CellTempFault_44 : 52|1@1+ (1,0) [0|1] ""  PC
 SG_ S2P_Bal_CellVoltFail_44 : 53|1@1+ (1,0) [0|1] ""  PC
 SG_ S2P_Bal_CloseBalInstruct_44 : 54|1@1+ (1,0) [0|1] ""  PC
 SG_ S2P_Bal_CCanTimeOut_44 : 55|1@1+ (1,0) [0|1] ""  PC
 SG_ S2P_Bal_CellOffLine_44 : 56|1@1+ (1,0) [0|1] ""  PC
 SG_ S2P_Bal_BalanceCircuitFault_44 : 57|1@1+ (1,0) [0|1] ""  PC
 SG_ S2P_Bal_CSCSourceVoltFault_44 : 58|1@1+ (1,0) [0|1] ""  PC
 SG_ S2P_Bal_CellVoltOverFault_44 : 59|1@1+ (1,0) [0|1] ""  PC
 SG_ S2P_Bal_CellVoltLowFault_44 : 60|1@1+ (1,0) [0|1] ""  PC
 SG_ S2P_Bal_CSCPCBTempFault_44 : 61|1@1+ (1,0) [0|1] ""  PC
 SG_ S2P_Bal_CSCSourceCurrLowFault_44 : 62|1@1+ (1,0) [0|1] ""  PC
 SG_ S2P_Bal_CSCSourceCurrOvrFault_44 : 63|1@1+ (1,0) [0|1] ""  PC

BO_ 2417487469 S2P_BL_Meg__45: 8 SBMU
 SG_ S2P_Bal_CSCNum_45 : 0|6@1+ (1,0) [0|63] ""  PC
 SG_ S2P_Bal_CellNum_45 : 6|6@1+ (1,0) [0|63] ""  PC
 SG_ S2P_Bal_Type_45 : 12|2@1+ (1,0) [0|3] ""  PC
 SG_ S2P_Bal_TimeRemain_45 : 14|9@1+ (1,0) [0|511] ""  PC
 SG_ S2P_Bal_DeltaVolt_45 : 23|10@1+ (1,0) [0|1023] ""  PC
 SG_ S2P_Bal_CSCPowerCurr_45 : 33|11@1+ (1,0) [0|2047] ""  PC
 SG_ S2P_Bal_TypeLevel_45 : 44|3@1+ (1,0) [0|7] ""  PC
 SG_ S2P_Bal_SystemStatus_45 : 47|2@1+ (1,0) [0|3] ""  PC
 SG_ S2P_Bal_Strategy_45 : 49|1@1+ (1,0) [0|1] ""  PC
 SG_ S2P_Bal_ForceBalMode_45 : 50|2@1+ (1,0) [0|3] ""  PC
 SG_ S2P_Bal_CellTempFault_45 : 52|1@1+ (1,0) [0|1] ""  PC
 SG_ S2P_Bal_CellVoltFail_45 : 53|1@1+ (1,0) [0|1] ""  PC
 SG_ S2P_Bal_CloseBalInstruct_45 : 54|1@1+ (1,0) [0|1] ""  PC
 SG_ S2P_Bal_CCanTimeOut_45 : 55|1@1+ (1,0) [0|1] ""  PC
 SG_ S2P_Bal_CellOffLine_45 : 56|1@1+ (1,0) [0|1] ""  PC
 SG_ S2P_Bal_BalanceCircuitFault_45 : 57|1@1+ (1,0) [0|1] ""  PC
 SG_ S2P_Bal_CSCSourceVoltFault_45 : 58|1@1+ (1,0) [0|1] ""  PC
 SG_ S2P_Bal_CellVoltOverFault_45 : 59|1@1+ (1,0) [0|1] ""  PC
 SG_ S2P_Bal_CellVoltLowFault_45 : 60|1@1+ (1,0) [0|1] ""  PC
 SG_ S2P_Bal_CSCPCBTempFault_45 : 61|1@1+ (1,0) [0|1] ""  PC
 SG_ S2P_Bal_CSCSourceCurrLowFault_45 : 62|1@1+ (1,0) [0|1] ""  PC
 SG_ S2P_Bal_CSCSourceCurrOvrFault_45 : 63|1@1+ (1,0) [0|1] ""  PC

BO_ 2417487470 S2P_BL_Meg__46: 8 SBMU
 SG_ S2P_Bal_CSCNum_46 : 0|6@1+ (1,0) [0|63] ""  PC
 SG_ S2P_Bal_CellNum_46 : 6|6@1+ (1,0) [0|63] ""  PC
 SG_ S2P_Bal_Type_46 : 12|2@1+ (1,0) [0|3] ""  PC
 SG_ S2P_Bal_TimeRemain_46 : 14|9@1+ (1,0) [0|511] ""  PC
 SG_ S2P_Bal_DeltaVolt_46 : 23|10@1+ (1,0) [0|1023] ""  PC
 SG_ S2P_Bal_CSCPowerCurr_46 : 33|11@1+ (1,0) [0|2047] ""  PC
 SG_ S2P_Bal_TypeLevel_46 : 44|3@1+ (1,0) [0|7] ""  PC
 SG_ S2P_Bal_SystemStatus_46 : 47|2@1+ (1,0) [0|3] ""  PC
 SG_ S2P_Bal_Strategy_46 : 49|1@1+ (1,0) [0|1] ""  PC
 SG_ S2P_Bal_ForceBalMode_46 : 50|2@1+ (1,0) [0|3] ""  PC
 SG_ S2P_Bal_CellTempFault_46 : 52|1@1+ (1,0) [0|1] ""  PC
 SG_ S2P_Bal_CellVoltFail_46 : 53|1@1+ (1,0) [0|1] ""  PC
 SG_ S2P_Bal_CloseBalInstruct_46 : 54|1@1+ (1,0) [0|1] ""  PC
 SG_ S2P_Bal_CCanTimeOut_46 : 55|1@1+ (1,0) [0|1] ""  PC
 SG_ S2P_Bal_CellOffLine_46 : 56|1@1+ (1,0) [0|1] ""  PC
 SG_ S2P_Bal_BalanceCircuitFault_46 : 57|1@1+ (1,0) [0|1] ""  PC
 SG_ S2P_Bal_CSCSourceVoltFault_46 : 58|1@1+ (1,0) [0|1] ""  PC
 SG_ S2P_Bal_CellVoltOverFault_46 : 59|1@1+ (1,0) [0|1] ""  PC
 SG_ S2P_Bal_CellVoltLowFault_46 : 60|1@1+ (1,0) [0|1] ""  PC
 SG_ S2P_Bal_CSCPCBTempFault_46 : 61|1@1+ (1,0) [0|1] ""  PC
 SG_ S2P_Bal_CSCSourceCurrLowFault_46 : 62|1@1+ (1,0) [0|1] ""  PC
 SG_ S2P_Bal_CSCSourceCurrOvrFault_46 : 63|1@1+ (1,0) [0|1] ""  PC

BO_ 2417487471 S2P_BL_Meg__47: 8 SBMU
 SG_ S2P_Bal_CSCNum_47 : 0|6@1+ (1,0) [0|63] ""  PC
 SG_ S2P_Bal_CellNum_47 : 6|6@1+ (1,0) [0|63] ""  PC
 SG_ S2P_Bal_Type_47 : 12|2@1+ (1,0) [0|3] ""  PC
 SG_ S2P_Bal_TimeRemain_47 : 14|9@1+ (1,0) [0|511] ""  PC
 SG_ S2P_Bal_DeltaVolt_47 : 23|10@1+ (1,0) [0|1023] ""  PC
 SG_ S2P_Bal_CSCPowerCurr_47 : 33|11@1+ (1,0) [0|2047] ""  PC
 SG_ S2P_Bal_TypeLevel_47 : 44|3@1+ (1,0) [0|7] ""  PC
 SG_ S2P_Bal_SystemStatus_47 : 47|2@1+ (1,0) [0|3] ""  PC
 SG_ S2P_Bal_Strategy_47 : 49|1@1+ (1,0) [0|1] ""  PC
 SG_ S2P_Bal_ForceBalMode_47 : 50|2@1+ (1,0) [0|3] ""  PC
 SG_ S2P_Bal_CellTempFault_47 : 52|1@1+ (1,0) [0|1] ""  PC
 SG_ S2P_Bal_CellVoltFail_47 : 53|1@1+ (1,0) [0|1] ""  PC
 SG_ S2P_Bal_CloseBalInstruct_47 : 54|1@1+ (1,0) [0|1] ""  PC
 SG_ S2P_Bal_CCanTimeOut_47 : 55|1@1+ (1,0) [0|1] ""  PC
 SG_ S2P_Bal_CellOffLine_47 : 56|1@1+ (1,0) [0|1] ""  PC
 SG_ S2P_Bal_BalanceCircuitFault_47 : 57|1@1+ (1,0) [0|1] ""  PC
 SG_ S2P_Bal_CSCSourceVoltFault_47 : 58|1@1+ (1,0) [0|1] ""  PC
 SG_ S2P_Bal_CellVoltOverFault_47 : 59|1@1+ (1,0) [0|1] ""  PC
 SG_ S2P_Bal_CellVoltLowFault_47 : 60|1@1+ (1,0) [0|1] ""  PC
 SG_ S2P_Bal_CSCPCBTempFault_47 : 61|1@1+ (1,0) [0|1] ""  PC
 SG_ S2P_Bal_CSCSourceCurrLowFault_47 : 62|1@1+ (1,0) [0|1] ""  PC
 SG_ S2P_Bal_CSCSourceCurrOvrFault_47 : 63|1@1+ (1,0) [0|1] ""  PC

BO_ 2417487472 S2P_BL_Meg__48: 8 SBMU
 SG_ S2P_Bal_CSCNum_48 : 0|6@1+ (1,0) [0|63] ""  PC
 SG_ S2P_Bal_CellNum_48 : 6|6@1+ (1,0) [0|63] ""  PC
 SG_ S2P_Bal_Type_48 : 12|2@1+ (1,0) [0|3] ""  PC
 SG_ S2P_Bal_TimeRemain_48 : 14|9@1+ (1,0) [0|511] ""  PC
 SG_ S2P_Bal_DeltaVolt_48 : 23|10@1+ (1,0) [0|1023] ""  PC
 SG_ S2P_Bal_CSCPowerCurr_48 : 33|11@1+ (1,0) [0|2047] ""  PC
 SG_ S2P_Bal_TypeLevel_48 : 44|3@1+ (1,0) [0|7] ""  PC
 SG_ S2P_Bal_SystemStatus_48 : 47|2@1+ (1,0) [0|3] ""  PC
 SG_ S2P_Bal_Strategy_48 : 49|1@1+ (1,0) [0|1] ""  PC
 SG_ S2P_Bal_ForceBalMode_48 : 50|2@1+ (1,0) [0|3] ""  PC
 SG_ S2P_Bal_CellTempFault_48 : 52|1@1+ (1,0) [0|1] ""  PC
 SG_ S2P_Bal_CellVoltFail_48 : 53|1@1+ (1,0) [0|1] ""  PC
 SG_ S2P_Bal_CloseBalInstruct_48 : 54|1@1+ (1,0) [0|1] ""  PC
 SG_ S2P_Bal_CCanTimeOut_48 : 55|1@1+ (1,0) [0|1] ""  PC
 SG_ S2P_Bal_CellOffLine_48 : 56|1@1+ (1,0) [0|1] ""  PC
 SG_ S2P_Bal_BalanceCircuitFault_48 : 57|1@1+ (1,0) [0|1] ""  PC
 SG_ S2P_Bal_CSCSourceVoltFault_48 : 58|1@1+ (1,0) [0|1] ""  PC
 SG_ S2P_Bal_CellVoltOverFault_48 : 59|1@1+ (1,0) [0|1] ""  PC
 SG_ S2P_Bal_CellVoltLowFault_48 : 60|1@1+ (1,0) [0|1] ""  PC
 SG_ S2P_Bal_CSCPCBTempFault_48 : 61|1@1+ (1,0) [0|1] ""  PC
 SG_ S2P_Bal_CSCSourceCurrLowFault_48 : 62|1@1+ (1,0) [0|1] ""  PC
 SG_ S2P_Bal_CSCSourceCurrOvrFault_48 : 63|1@1+ (1,0) [0|1] ""  PC

BO_ 2417487473 S2P_BL_Meg__49: 8 SBMU
 SG_ S2P_Bal_CSCNum_49 : 0|6@1+ (1,0) [0|63] ""  PC
 SG_ S2P_Bal_CellNum_49 : 6|6@1+ (1,0) [0|63] ""  PC
 SG_ S2P_Bal_Type_49 : 12|2@1+ (1,0) [0|3] ""  PC
 SG_ S2P_Bal_TimeRemain_49 : 14|9@1+ (1,0) [0|511] ""  PC
 SG_ S2P_Bal_DeltaVolt_49 : 23|10@1+ (1,0) [0|1023] ""  PC
 SG_ S2P_Bal_CSCPowerCurr_49 : 33|11@1+ (1,0) [0|2047] ""  PC
 SG_ S2P_Bal_TypeLevel_49 : 44|3@1+ (1,0) [0|7] ""  PC
 SG_ S2P_Bal_SystemStatus_49 : 47|2@1+ (1,0) [0|3] ""  PC
 SG_ S2P_Bal_Strategy_49 : 49|1@1+ (1,0) [0|1] ""  PC
 SG_ S2P_Bal_ForceBalMode_49 : 50|2@1+ (1,0) [0|3] ""  PC
 SG_ S2P_Bal_CellTempFault_49 : 52|1@1+ (1,0) [0|1] ""  PC
 SG_ S2P_Bal_CellVoltFail_49 : 53|1@1+ (1,0) [0|1] ""  PC
 SG_ S2P_Bal_CloseBalInstruct_49 : 54|1@1+ (1,0) [0|1] ""  PC
 SG_ S2P_Bal_CCanTimeOut_49 : 55|1@1+ (1,0) [0|1] ""  PC
 SG_ S2P_Bal_CellOffLine_49 : 56|1@1+ (1,0) [0|1] ""  PC
 SG_ S2P_Bal_BalanceCircuitFault_49 : 57|1@1+ (1,0) [0|1] ""  PC
 SG_ S2P_Bal_CSCSourceVoltFault_49 : 58|1@1+ (1,0) [0|1] ""  PC
 SG_ S2P_Bal_CellVoltOverFault_49 : 59|1@1+ (1,0) [0|1] ""  PC
 SG_ S2P_Bal_CellVoltLowFault_49 : 60|1@1+ (1,0) [0|1] ""  PC
 SG_ S2P_Bal_CSCPCBTempFault_49 : 61|1@1+ (1,0) [0|1] ""  PC
 SG_ S2P_Bal_CSCSourceCurrLowFault_49 : 62|1@1+ (1,0) [0|1] ""  PC
 SG_ S2P_Bal_CSCSourceCurrOvrFault_49 : 63|1@1+ (1,0) [0|1] ""  PC

BO_ 2417487474 S2P_BL_Meg__50: 8 SBMU
 SG_ S2P_Bal_CSCNum_50 : 0|6@1+ (1,0) [0|63] ""  PC
 SG_ S2P_Bal_CellNum_50 : 6|6@1+ (1,0) [0|63] ""  PC
 SG_ S2P_Bal_Type_50 : 12|2@1+ (1,0) [0|3] ""  PC
 SG_ S2P_Bal_TimeRemain_50 : 14|9@1+ (1,0) [0|511] ""  PC
 SG_ S2P_Bal_DeltaVolt_50 : 23|10@1+ (1,0) [0|1023] ""  PC
 SG_ S2P_Bal_CSCPowerCurr_50 : 33|11@1+ (1,0) [0|2047] ""  PC
 SG_ S2P_Bal_TypeLevel_50 : 44|3@1+ (1,0) [0|7] ""  PC
 SG_ S2P_Bal_SystemStatus_50 : 47|2@1+ (1,0) [0|3] ""  PC
 SG_ S2P_Bal_Strategy_50 : 49|1@1+ (1,0) [0|1] ""  PC
 SG_ S2P_Bal_ForceBalMode_50 : 50|2@1+ (1,0) [0|3] ""  PC
 SG_ S2P_Bal_CellTempFault_50 : 52|1@1+ (1,0) [0|1] ""  PC
 SG_ S2P_Bal_CellVoltFail_50 : 53|1@1+ (1,0) [0|1] ""  PC
 SG_ S2P_Bal_CloseBalInstruct_50 : 54|1@1+ (1,0) [0|1] ""  PC
 SG_ S2P_Bal_CCanTimeOut_50 : 55|1@1+ (1,0) [0|1] ""  PC
 SG_ S2P_Bal_CellOffLine_50 : 56|1@1+ (1,0) [0|1] ""  PC
 SG_ S2P_Bal_BalanceCircuitFault_50 : 57|1@1+ (1,0) [0|1] ""  PC
 SG_ S2P_Bal_CSCSourceVoltFault_50 : 58|1@1+ (1,0) [0|1] ""  PC
 SG_ S2P_Bal_CellVoltOverFault_50 : 59|1@1+ (1,0) [0|1] ""  PC
 SG_ S2P_Bal_CellVoltLowFault_50 : 60|1@1+ (1,0) [0|1] ""  PC
 SG_ S2P_Bal_CSCPCBTempFault_50 : 61|1@1+ (1,0) [0|1] ""  PC
 SG_ S2P_Bal_CSCSourceCurrLowFault_50 : 62|1@1+ (1,0) [0|1] ""  PC
 SG_ S2P_Bal_CSCSourceCurrOvrFault_50 : 63|1@1+ (1,0) [0|1] ""  PC

BO_ 2417487475 S2P_BL_Meg__51: 8 SBMU
 SG_ S2P_Bal_CSCNum_51 : 0|6@1+ (1,0) [0|63] ""  PC
 SG_ S2P_Bal_CellNum_51 : 6|6@1+ (1,0) [0|63] ""  PC
 SG_ S2P_Bal_Type_51 : 12|2@1+ (1,0) [0|3] ""  PC
 SG_ S2P_Bal_TimeRemain_51 : 14|9@1+ (1,0) [0|511] ""  PC
 SG_ S2P_Bal_DeltaVolt_51 : 23|10@1+ (1,0) [0|1023] ""  PC
 SG_ S2P_Bal_CSCPowerCurr_51 : 33|11@1+ (1,0) [0|2047] ""  PC
 SG_ S2P_Bal_TypeLevel_51 : 44|3@1+ (1,0) [0|7] ""  PC
 SG_ S2P_Bal_SystemStatus_51 : 47|2@1+ (1,0) [0|3] ""  PC
 SG_ S2P_Bal_Strategy_51 : 49|1@1+ (1,0) [0|1] ""  PC
 SG_ S2P_Bal_ForceBalMode_51 : 50|2@1+ (1,0) [0|3] ""  PC
 SG_ S2P_Bal_CellTempFault_51 : 52|1@1+ (1,0) [0|1] ""  PC
 SG_ S2P_Bal_CellVoltFail_51 : 53|1@1+ (1,0) [0|1] ""  PC
 SG_ S2P_Bal_CloseBalInstruct_51 : 54|1@1+ (1,0) [0|1] ""  PC
 SG_ S2P_Bal_CCanTimeOut_51 : 55|1@1+ (1,0) [0|1] ""  PC
 SG_ S2P_Bal_CellOffLine_51 : 56|1@1+ (1,0) [0|1] ""  PC
 SG_ S2P_Bal_BalanceCircuitFault_51 : 57|1@1+ (1,0) [0|1] ""  PC
 SG_ S2P_Bal_CSCSourceVoltFault_51 : 58|1@1+ (1,0) [0|1] ""  PC
 SG_ S2P_Bal_CellVoltOverFault_51 : 59|1@1+ (1,0) [0|1] ""  PC
 SG_ S2P_Bal_CellVoltLowFault_51 : 60|1@1+ (1,0) [0|1] ""  PC
 SG_ S2P_Bal_CSCPCBTempFault_51 : 61|1@1+ (1,0) [0|1] ""  PC
 SG_ S2P_Bal_CSCSourceCurrLowFault_51 : 62|1@1+ (1,0) [0|1] ""  PC
 SG_ S2P_Bal_CSCSourceCurrOvrFault_51 : 63|1@1+ (1,0) [0|1] ""  PC

BO_ 2417487476 S2P_BL_Meg__52: 8 SBMU
 SG_ S2P_Bal_CSCNum_52 : 0|6@1+ (1,0) [0|63] ""  PC
 SG_ S2P_Bal_CellNum_52 : 6|6@1+ (1,0) [0|63] ""  PC
 SG_ S2P_Bal_Type_52 : 12|2@1+ (1,0) [0|3] ""  PC
 SG_ S2P_Bal_TimeRemain_52 : 14|9@1+ (1,0) [0|511] ""  PC
 SG_ S2P_Bal_DeltaVolt_52 : 23|10@1+ (1,0) [0|1023] ""  PC
 SG_ S2P_Bal_CSCPowerCurr_52 : 33|11@1+ (1,0) [0|2047] ""  PC
 SG_ S2P_Bal_TypeLevel_52 : 44|3@1+ (1,0) [0|7] ""  PC
 SG_ S2P_Bal_SystemStatus_52 : 47|2@1+ (1,0) [0|3] ""  PC
 SG_ S2P_Bal_Strategy_52 : 49|1@1+ (1,0) [0|1] ""  PC
 SG_ S2P_Bal_ForceBalMode_52 : 50|2@1+ (1,0) [0|3] ""  PC
 SG_ S2P_Bal_CellTempFault_52 : 52|1@1+ (1,0) [0|1] ""  PC
 SG_ S2P_Bal_CellVoltFail_52 : 53|1@1+ (1,0) [0|1] ""  PC
 SG_ S2P_Bal_CloseBalInstruct_52 : 54|1@1+ (1,0) [0|1] ""  PC
 SG_ S2P_Bal_CCanTimeOut_52 : 55|1@1+ (1,0) [0|1] ""  PC
 SG_ S2P_Bal_CellOffLine_52 : 56|1@1+ (1,0) [0|1] ""  PC
 SG_ S2P_Bal_BalanceCircuitFault_52 : 57|1@1+ (1,0) [0|1] ""  PC
 SG_ S2P_Bal_CSCSourceVoltFault_52 : 58|1@1+ (1,0) [0|1] ""  PC
 SG_ S2P_Bal_CellVoltOverFault_52 : 59|1@1+ (1,0) [0|1] ""  PC
 SG_ S2P_Bal_CellVoltLowFault_52 : 60|1@1+ (1,0) [0|1] ""  PC
 SG_ S2P_Bal_CSCPCBTempFault_52 : 61|1@1+ (1,0) [0|1] ""  PC
 SG_ S2P_Bal_CSCSourceCurrLowFault_52 : 62|1@1+ (1,0) [0|1] ""  PC
 SG_ S2P_Bal_CSCSourceCurrOvrFault_52 : 63|1@1+ (1,0) [0|1] ""  PC

BO_ 2417487477 S2P_BL_Meg__53: 8 SBMU
 SG_ S2P_Bal_CSCNum_53 : 0|6@1+ (1,0) [0|63] ""  PC
 SG_ S2P_Bal_CellNum_53 : 6|6@1+ (1,0) [0|63] ""  PC
 SG_ S2P_Bal_Type_53 : 12|2@1+ (1,0) [0|3] ""  PC
 SG_ S2P_Bal_TimeRemain_53 : 14|9@1+ (1,0) [0|511] ""  PC
 SG_ S2P_Bal_DeltaVolt_53 : 23|10@1+ (1,0) [0|1023] ""  PC
 SG_ S2P_Bal_CSCPowerCurr_53 : 33|11@1+ (1,0) [0|2047] ""  PC
 SG_ S2P_Bal_TypeLevel_53 : 44|3@1+ (1,0) [0|7] ""  PC
 SG_ S2P_Bal_SystemStatus_53 : 47|2@1+ (1,0) [0|3] ""  PC
 SG_ S2P_Bal_Strategy_53 : 49|1@1+ (1,0) [0|1] ""  PC
 SG_ S2P_Bal_ForceBalMode_53 : 50|2@1+ (1,0) [0|3] ""  PC
 SG_ S2P_Bal_CellTempFault_53 : 52|1@1+ (1,0) [0|1] ""  PC
 SG_ S2P_Bal_CellVoltFail_53 : 53|1@1+ (1,0) [0|1] ""  PC
 SG_ S2P_Bal_CloseBalInstruct_53 : 54|1@1+ (1,0) [0|1] ""  PC
 SG_ S2P_Bal_CCanTimeOut_53 : 55|1@1+ (1,0) [0|1] ""  PC
 SG_ S2P_Bal_CellOffLine_53 : 56|1@1+ (1,0) [0|1] ""  PC
 SG_ S2P_Bal_BalanceCircuitFault_53 : 57|1@1+ (1,0) [0|1] ""  PC
 SG_ S2P_Bal_CSCSourceVoltFault_53 : 58|1@1+ (1,0) [0|1] ""  PC
 SG_ S2P_Bal_CellVoltOverFault_53 : 59|1@1+ (1,0) [0|1] ""  PC
 SG_ S2P_Bal_CellVoltLowFault_53 : 60|1@1+ (1,0) [0|1] ""  PC
 SG_ S2P_Bal_CSCPCBTempFault_53 : 61|1@1+ (1,0) [0|1] ""  PC
 SG_ S2P_Bal_CSCSourceCurrLowFault_53 : 62|1@1+ (1,0) [0|1] ""  PC
 SG_ S2P_Bal_CSCSourceCurrOvrFault_53 : 63|1@1+ (1,0) [0|1] ""  PC

BO_ 2417487478 S2P_BL_Meg__54: 8 SBMU
 SG_ S2P_Bal_CSCNum_54 : 0|6@1+ (1,0) [0|63] ""  PC
 SG_ S2P_Bal_CellNum_54 : 6|6@1+ (1,0) [0|63] ""  PC
 SG_ S2P_Bal_Type_54 : 12|2@1+ (1,0) [0|3] ""  PC
 SG_ S2P_Bal_TimeRemain_54 : 14|9@1+ (1,0) [0|511] ""  PC
 SG_ S2P_Bal_DeltaVolt_54 : 23|10@1+ (1,0) [0|1023] ""  PC
 SG_ S2P_Bal_CSCPowerCurr_54 : 33|11@1+ (1,0) [0|2047] ""  PC
 SG_ S2P_Bal_TypeLevel_54 : 44|3@1+ (1,0) [0|7] ""  PC
 SG_ S2P_Bal_SystemStatus_54 : 47|2@1+ (1,0) [0|3] ""  PC
 SG_ S2P_Bal_Strategy_54 : 49|1@1+ (1,0) [0|1] ""  PC
 SG_ S2P_Bal_ForceBalMode_54 : 50|2@1+ (1,0) [0|3] ""  PC
 SG_ S2P_Bal_CellTempFault_54 : 52|1@1+ (1,0) [0|1] ""  PC
 SG_ S2P_Bal_CellVoltFail_54 : 53|1@1+ (1,0) [0|1] ""  PC
 SG_ S2P_Bal_CloseBalInstruct_54 : 54|1@1+ (1,0) [0|1] ""  PC
 SG_ S2P_Bal_CCanTimeOut_54 : 55|1@1+ (1,0) [0|1] ""  PC
 SG_ S2P_Bal_CellOffLine_54 : 56|1@1+ (1,0) [0|1] ""  PC
 SG_ S2P_Bal_BalanceCircuitFault_54 : 57|1@1+ (1,0) [0|1] ""  PC
 SG_ S2P_Bal_CSCSourceVoltFault_54 : 58|1@1+ (1,0) [0|1] ""  PC
 SG_ S2P_Bal_CellVoltOverFault_54 : 59|1@1+ (1,0) [0|1] ""  PC
 SG_ S2P_Bal_CellVoltLowFault_54 : 60|1@1+ (1,0) [0|1] ""  PC
 SG_ S2P_Bal_CSCPCBTempFault_54 : 61|1@1+ (1,0) [0|1] ""  PC
 SG_ S2P_Bal_CSCSourceCurrLowFault_54 : 62|1@1+ (1,0) [0|1] ""  PC
 SG_ S2P_Bal_CSCSourceCurrOvrFault_54 : 63|1@1+ (1,0) [0|1] ""  PC

BO_ 2417487479 S2P_BL_Meg__55: 8 SBMU
 SG_ S2P_Bal_CSCNum_55 : 0|6@1+ (1,0) [0|63] ""  PC
 SG_ S2P_Bal_CellNum_55 : 6|6@1+ (1,0) [0|63] ""  PC
 SG_ S2P_Bal_Type_55 : 12|2@1+ (1,0) [0|3] ""  PC
 SG_ S2P_Bal_TimeRemain_55 : 14|9@1+ (1,0) [0|511] ""  PC
 SG_ S2P_Bal_DeltaVolt_55 : 23|10@1+ (1,0) [0|1023] ""  PC
 SG_ S2P_Bal_CSCPowerCurr_55 : 33|11@1+ (1,0) [0|2047] ""  PC
 SG_ S2P_Bal_TypeLevel_55 : 44|3@1+ (1,0) [0|7] ""  PC
 SG_ S2P_Bal_SystemStatus_55 : 47|2@1+ (1,0) [0|3] ""  PC
 SG_ S2P_Bal_Strategy_55 : 49|1@1+ (1,0) [0|1] ""  PC
 SG_ S2P_Bal_ForceBalMode_55 : 50|2@1+ (1,0) [0|3] ""  PC
 SG_ S2P_Bal_CellTempFault_55 : 52|1@1+ (1,0) [0|1] ""  PC
 SG_ S2P_Bal_CellVoltFail_55 : 53|1@1+ (1,0) [0|1] ""  PC
 SG_ S2P_Bal_CloseBalInstruct_55 : 54|1@1+ (1,0) [0|1] ""  PC
 SG_ S2P_Bal_CCanTimeOut_55 : 55|1@1+ (1,0) [0|1] ""  PC
 SG_ S2P_Bal_CellOffLine_55 : 56|1@1+ (1,0) [0|1] ""  PC
 SG_ S2P_Bal_BalanceCircuitFault_55 : 57|1@1+ (1,0) [0|1] ""  PC
 SG_ S2P_Bal_CSCSourceVoltFault_55 : 58|1@1+ (1,0) [0|1] ""  PC
 SG_ S2P_Bal_CellVoltOverFault_55 : 59|1@1+ (1,0) [0|1] ""  PC
 SG_ S2P_Bal_CellVoltLowFault_55 : 60|1@1+ (1,0) [0|1] ""  PC
 SG_ S2P_Bal_CSCPCBTempFault_55 : 61|1@1+ (1,0) [0|1] ""  PC
 SG_ S2P_Bal_CSCSourceCurrLowFault_55 : 62|1@1+ (1,0) [0|1] ""  PC
 SG_ S2P_Bal_CSCSourceCurrOvrFault_55 : 63|1@1+ (1,0) [0|1] ""  PC

BO_ 2417487480 S2P_BL_Meg__56: 8 SBMU
 SG_ S2P_Bal_CSCNum_56 : 0|6@1+ (1,0) [0|63] ""  PC
 SG_ S2P_Bal_CellNum_56 : 6|6@1+ (1,0) [0|63] ""  PC
 SG_ S2P_Bal_Type_56 : 12|2@1+ (1,0) [0|3] ""  PC
 SG_ S2P_Bal_TimeRemain_56 : 14|9@1+ (1,0) [0|511] ""  PC
 SG_ S2P_Bal_DeltaVolt_56 : 23|10@1+ (1,0) [0|1023] ""  PC
 SG_ S2P_Bal_CSCPowerCurr_56 : 33|11@1+ (1,0) [0|2047] ""  PC
 SG_ S2P_Bal_TypeLevel_56 : 44|3@1+ (1,0) [0|7] ""  PC
 SG_ S2P_Bal_SystemStatus_56 : 47|2@1+ (1,0) [0|3] ""  PC
 SG_ S2P_Bal_Strategy_56 : 49|1@1+ (1,0) [0|1] ""  PC
 SG_ S2P_Bal_ForceBalMode_56 : 50|2@1+ (1,0) [0|3] ""  PC
 SG_ S2P_Bal_CellTempFault_56 : 52|1@1+ (1,0) [0|1] ""  PC
 SG_ S2P_Bal_CellVoltFail_56 : 53|1@1+ (1,0) [0|1] ""  PC
 SG_ S2P_Bal_CloseBalInstruct_56 : 54|1@1+ (1,0) [0|1] ""  PC
 SG_ S2P_Bal_CCanTimeOut_56 : 55|1@1+ (1,0) [0|1] ""  PC
 SG_ S2P_Bal_CellOffLine_56 : 56|1@1+ (1,0) [0|1] ""  PC
 SG_ S2P_Bal_BalanceCircuitFault_56 : 57|1@1+ (1,0) [0|1] ""  PC
 SG_ S2P_Bal_CSCSourceVoltFault_56 : 58|1@1+ (1,0) [0|1] ""  PC
 SG_ S2P_Bal_CellVoltOverFault_56 : 59|1@1+ (1,0) [0|1] ""  PC
 SG_ S2P_Bal_CellVoltLowFault_56 : 60|1@1+ (1,0) [0|1] ""  PC
 SG_ S2P_Bal_CSCPCBTempFault_56 : 61|1@1+ (1,0) [0|1] ""  PC
 SG_ S2P_Bal_CSCSourceCurrLowFault_56 : 62|1@1+ (1,0) [0|1] ""  PC
 SG_ S2P_Bal_CSCSourceCurrOvrFault_56 : 63|1@1+ (1,0) [0|1] ""  PC

BO_ 2417487481 S2P_BL_Meg__57: 8 SBMU
 SG_ S2P_Bal_CSCNum_57 : 0|6@1+ (1,0) [0|63] ""  PC
 SG_ S2P_Bal_CellNum_57 : 6|6@1+ (1,0) [0|63] ""  PC
 SG_ S2P_Bal_Type_57 : 12|2@1+ (1,0) [0|3] ""  PC
 SG_ S2P_Bal_TimeRemain_57 : 14|9@1+ (1,0) [0|511] ""  PC
 SG_ S2P_Bal_DeltaVolt_57 : 23|10@1+ (1,0) [0|1023] ""  PC
 SG_ S2P_Bal_CSCPowerCurr_57 : 33|11@1+ (1,0) [0|2047] ""  PC
 SG_ S2P_Bal_TypeLevel_57 : 44|3@1+ (1,0) [0|7] ""  PC
 SG_ S2P_Bal_SystemStatus_57 : 47|2@1+ (1,0) [0|3] ""  PC
 SG_ S2P_Bal_Strategy_57 : 49|1@1+ (1,0) [0|1] ""  PC
 SG_ S2P_Bal_ForceBalMode_57 : 50|2@1+ (1,0) [0|3] ""  PC
 SG_ S2P_Bal_CellTempFault_57 : 52|1@1+ (1,0) [0|1] ""  PC
 SG_ S2P_Bal_CellVoltFail_57 : 53|1@1+ (1,0) [0|1] ""  PC
 SG_ S2P_Bal_CloseBalInstruct_57 : 54|1@1+ (1,0) [0|1] ""  PC
 SG_ S2P_Bal_CCanTimeOut_57 : 55|1@1+ (1,0) [0|1] ""  PC
 SG_ S2P_Bal_CellOffLine_57 : 56|1@1+ (1,0) [0|1] ""  PC
 SG_ S2P_Bal_BalanceCircuitFault_57 : 57|1@1+ (1,0) [0|1] ""  PC
 SG_ S2P_Bal_CSCSourceVoltFault_57 : 58|1@1+ (1,0) [0|1] ""  PC
 SG_ S2P_Bal_CellVoltOverFault_57 : 59|1@1+ (1,0) [0|1] ""  PC
 SG_ S2P_Bal_CellVoltLowFault_57 : 60|1@1+ (1,0) [0|1] ""  PC
 SG_ S2P_Bal_CSCPCBTempFault_57 : 61|1@1+ (1,0) [0|1] ""  PC
 SG_ S2P_Bal_CSCSourceCurrLowFault_57 : 62|1@1+ (1,0) [0|1] ""  PC
 SG_ S2P_Bal_CSCSourceCurrOvrFault_57 : 63|1@1+ (1,0) [0|1] ""  PC

BO_ 2417487482 S2P_BL_Meg__58: 8 SBMU
 SG_ S2P_Bal_CSCNum_58 : 0|6@1+ (1,0) [0|63] ""  PC
 SG_ S2P_Bal_CellNum_58 : 6|6@1+ (1,0) [0|63] ""  PC
 SG_ S2P_Bal_Type_58 : 12|2@1+ (1,0) [0|3] ""  PC
 SG_ S2P_Bal_TimeRemain_58 : 14|9@1+ (1,0) [0|511] ""  PC
 SG_ S2P_Bal_DeltaVolt_58 : 23|10@1+ (1,0) [0|1023] ""  PC
 SG_ S2P_Bal_CSCPowerCurr_58 : 33|11@1+ (1,0) [0|2047] ""  PC
 SG_ S2P_Bal_TypeLevel_58 : 44|3@1+ (1,0) [0|7] ""  PC
 SG_ S2P_Bal_SystemStatus_58 : 47|2@1+ (1,0) [0|3] ""  PC
 SG_ S2P_Bal_Strategy_58 : 49|1@1+ (1,0) [0|1] ""  PC
 SG_ S2P_Bal_ForceBalMode_58 : 50|2@1+ (1,0) [0|3] ""  PC
 SG_ S2P_Bal_CellTempFault_58 : 52|1@1+ (1,0) [0|1] ""  PC
 SG_ S2P_Bal_CellVoltFail_58 : 53|1@1+ (1,0) [0|1] ""  PC
 SG_ S2P_Bal_CloseBalInstruct_58 : 54|1@1+ (1,0) [0|1] ""  PC
 SG_ S2P_Bal_CCanTimeOut_58 : 55|1@1+ (1,0) [0|1] ""  PC
 SG_ S2P_Bal_CellOffLine_58 : 56|1@1+ (1,0) [0|1] ""  PC
 SG_ S2P_Bal_BalanceCircuitFault_58 : 57|1@1+ (1,0) [0|1] ""  PC
 SG_ S2P_Bal_CSCSourceVoltFault_58 : 58|1@1+ (1,0) [0|1] ""  PC
 SG_ S2P_Bal_CellVoltOverFault_58 : 59|1@1+ (1,0) [0|1] ""  PC
 SG_ S2P_Bal_CellVoltLowFault_58 : 60|1@1+ (1,0) [0|1] ""  PC
 SG_ S2P_Bal_CSCPCBTempFault_58 : 61|1@1+ (1,0) [0|1] ""  PC
 SG_ S2P_Bal_CSCSourceCurrLowFault_58 : 62|1@1+ (1,0) [0|1] ""  PC
 SG_ S2P_Bal_CSCSourceCurrOvrFault_58 : 63|1@1+ (1,0) [0|1] ""  PC

BO_ 2417487483 S2P_BL_Meg__59: 8 SBMU
 SG_ S2P_Bal_CSCNum_59 : 0|6@1+ (1,0) [0|63] ""  PC
 SG_ S2P_Bal_CellNum_59 : 6|6@1+ (1,0) [0|63] ""  PC
 SG_ S2P_Bal_Type_59 : 12|2@1+ (1,0) [0|3] ""  PC
 SG_ S2P_Bal_TimeRemain_59 : 14|9@1+ (1,0) [0|511] ""  PC
 SG_ S2P_Bal_DeltaVolt_59 : 23|10@1+ (1,0) [0|1023] ""  PC
 SG_ S2P_Bal_CSCPowerCurr_59 : 33|11@1+ (1,0) [0|2047] ""  PC
 SG_ S2P_Bal_TypeLevel_59 : 44|3@1+ (1,0) [0|7] ""  PC
 SG_ S2P_Bal_SystemStatus_59 : 47|2@1+ (1,0) [0|3] ""  PC
 SG_ S2P_Bal_Strategy_59 : 49|1@1+ (1,0) [0|1] ""  PC
 SG_ S2P_Bal_ForceBalMode_59 : 50|2@1+ (1,0) [0|3] ""  PC
 SG_ S2P_Bal_CellTempFault_59 : 52|1@1+ (1,0) [0|1] ""  PC
 SG_ S2P_Bal_CellVoltFail_59 : 53|1@1+ (1,0) [0|1] ""  PC
 SG_ S2P_Bal_CloseBalInstruct_59 : 54|1@1+ (1,0) [0|1] ""  PC
 SG_ S2P_Bal_CCanTimeOut_59 : 55|1@1+ (1,0) [0|1] ""  PC
 SG_ S2P_Bal_CellOffLine_59 : 56|1@1+ (1,0) [0|1] ""  PC
 SG_ S2P_Bal_BalanceCircuitFault_59 : 57|1@1+ (1,0) [0|1] ""  PC
 SG_ S2P_Bal_CSCSourceVoltFault_59 : 58|1@1+ (1,0) [0|1] ""  PC
 SG_ S2P_Bal_CellVoltOverFault_59 : 59|1@1+ (1,0) [0|1] ""  PC
 SG_ S2P_Bal_CellVoltLowFault_59 : 60|1@1+ (1,0) [0|1] ""  PC
 SG_ S2P_Bal_CSCPCBTempFault_59 : 61|1@1+ (1,0) [0|1] ""  PC
 SG_ S2P_Bal_CSCSourceCurrLowFault_59 : 62|1@1+ (1,0) [0|1] ""  PC
 SG_ S2P_Bal_CSCSourceCurrOvrFault_59 : 63|1@1+ (1,0) [0|1] ""  PC

BO_ 2417487484 S2P_BL_Meg__60: 8 SBMU
 SG_ S2P_Bal_CSCNum_60 : 0|6@1+ (1,0) [0|63] ""  PC
 SG_ S2P_Bal_CellNum_60 : 6|6@1+ (1,0) [0|63] ""  PC
 SG_ S2P_Bal_Type_60 : 12|2@1+ (1,0) [0|3] ""  PC
 SG_ S2P_Bal_TimeRemain_60 : 14|9@1+ (1,0) [0|511] ""  PC
 SG_ S2P_Bal_DeltaVolt_60 : 23|10@1+ (1,0) [0|1023] ""  PC
 SG_ S2P_Bal_CSCPowerCurr_60 : 33|11@1+ (1,0) [0|2047] ""  PC
 SG_ S2P_Bal_TypeLevel_60 : 44|3@1+ (1,0) [0|7] ""  PC
 SG_ S2P_Bal_SystemStatus_60 : 47|2@1+ (1,0) [0|3] ""  PC
 SG_ S2P_Bal_Strategy_60 : 49|1@1+ (1,0) [0|1] ""  PC
 SG_ S2P_Bal_ForceBalMode_60 : 50|2@1+ (1,0) [0|3] ""  PC
 SG_ S2P_Bal_CellTempFault_60 : 52|1@1+ (1,0) [0|1] ""  PC
 SG_ S2P_Bal_CellVoltFail_60 : 53|1@1+ (1,0) [0|1] ""  PC
 SG_ S2P_Bal_CloseBalInstruct_60 : 54|1@1+ (1,0) [0|1] ""  PC
 SG_ S2P_Bal_CCanTimeOut_60 : 55|1@1+ (1,0) [0|1] ""  PC
 SG_ S2P_Bal_CellOffLine_60 : 56|1@1+ (1,0) [0|1] ""  PC
 SG_ S2P_Bal_BalanceCircuitFault_60 : 57|1@1+ (1,0) [0|1] ""  PC
 SG_ S2P_Bal_CSCSourceVoltFault_60 : 58|1@1+ (1,0) [0|1] ""  PC
 SG_ S2P_Bal_CellVoltOverFault_60 : 59|1@1+ (1,0) [0|1] ""  PC
 SG_ S2P_Bal_CellVoltLowFault_60 : 60|1@1+ (1,0) [0|1] ""  PC
 SG_ S2P_Bal_CSCPCBTempFault_60 : 61|1@1+ (1,0) [0|1] ""  PC
 SG_ S2P_Bal_CSCSourceCurrLowFault_60 : 62|1@1+ (1,0) [0|1] ""  PC
 SG_ S2P_Bal_CSCSourceCurrOvrFault_60 : 63|1@1+ (1,0) [0|1] ""  PC

BO_ 2417487485 S2P_BL_Meg__61: 8 SBMU
 SG_ S2P_Bal_CSCNum_61 : 0|6@1+ (1,0) [0|63] ""  PC
 SG_ S2P_Bal_CellNum_61 : 6|6@1+ (1,0) [0|63] ""  PC
 SG_ S2P_Bal_Type_61 : 12|2@1+ (1,0) [0|3] ""  PC
 SG_ S2P_Bal_TimeRemain_61 : 14|9@1+ (1,0) [0|511] ""  PC
 SG_ S2P_Bal_DeltaVolt_61 : 23|10@1+ (1,0) [0|1023] ""  PC
 SG_ S2P_Bal_CSCPowerCurr_61 : 33|11@1+ (1,0) [0|2047] ""  PC
 SG_ S2P_Bal_TypeLevel_61 : 44|3@1+ (1,0) [0|7] ""  PC
 SG_ S2P_Bal_SystemStatus_61 : 47|2@1+ (1,0) [0|3] ""  PC
 SG_ S2P_Bal_Strategy_61 : 49|1@1+ (1,0) [0|1] ""  PC
 SG_ S2P_Bal_ForceBalMode_61 : 50|2@1+ (1,0) [0|3] ""  PC
 SG_ S2P_Bal_CellTempFault_61 : 52|1@1+ (1,0) [0|1] ""  PC
 SG_ S2P_Bal_CellVoltFail_61 : 53|1@1+ (1,0) [0|1] ""  PC
 SG_ S2P_Bal_CloseBalInstruct_61 : 54|1@1+ (1,0) [0|1] ""  PC
 SG_ S2P_Bal_CCanTimeOut_61 : 55|1@1+ (1,0) [0|1] ""  PC
 SG_ S2P_Bal_CellOffLine_61 : 56|1@1+ (1,0) [0|1] ""  PC
 SG_ S2P_Bal_BalanceCircuitFault_61 : 57|1@1+ (1,0) [0|1] ""  PC
 SG_ S2P_Bal_CSCSourceVoltFault_61 : 58|1@1+ (1,0) [0|1] ""  PC
 SG_ S2P_Bal_CellVoltOverFault_61 : 59|1@1+ (1,0) [0|1] ""  PC
 SG_ S2P_Bal_CellVoltLowFault_61 : 60|1@1+ (1,0) [0|1] ""  PC
 SG_ S2P_Bal_CSCPCBTempFault_61 : 61|1@1+ (1,0) [0|1] ""  PC
 SG_ S2P_Bal_CSCSourceCurrLowFault_61 : 62|1@1+ (1,0) [0|1] ""  PC
 SG_ S2P_Bal_CSCSourceCurrOvrFault_61 : 63|1@1+ (1,0) [0|1] ""  PC

BO_ 2417487486 S2P_BL_Meg__62: 8 SBMU
 SG_ S2P_Bal_CSCNum_62 : 0|6@1+ (1,0) [0|63] ""  PC
 SG_ S2P_Bal_CellNum_62 : 6|6@1+ (1,0) [0|63] ""  PC
 SG_ S2P_Bal_Type_62 : 12|2@1+ (1,0) [0|3] ""  PC
 SG_ S2P_Bal_TimeRemain_62 : 14|9@1+ (1,0) [0|511] ""  PC
 SG_ S2P_Bal_DeltaVolt_62 : 23|10@1+ (1,0) [0|1023] ""  PC
 SG_ S2P_Bal_CSCPowerCurr_62 : 33|11@1+ (1,0) [0|2047] ""  PC
 SG_ S2P_Bal_TypeLevel_62 : 44|3@1+ (1,0) [0|7] ""  PC
 SG_ S2P_Bal_SystemStatus_62 : 47|2@1+ (1,0) [0|3] ""  PC
 SG_ S2P_Bal_Strategy_62 : 49|1@1+ (1,0) [0|1] ""  PC
 SG_ S2P_Bal_ForceBalMode_62 : 50|2@1+ (1,0) [0|3] ""  PC
 SG_ S2P_Bal_CellTempFault_62 : 52|1@1+ (1,0) [0|1] ""  PC
 SG_ S2P_Bal_CellVoltFail_62 : 53|1@1+ (1,0) [0|1] ""  PC
 SG_ S2P_Bal_CloseBalInstruct_62 : 54|1@1+ (1,0) [0|1] ""  PC
 SG_ S2P_Bal_CCanTimeOut_62 : 55|1@1+ (1,0) [0|1] ""  PC
 SG_ S2P_Bal_CellOffLine_62 : 56|1@1+ (1,0) [0|1] ""  PC
 SG_ S2P_Bal_BalanceCircuitFault_62 : 57|1@1+ (1,0) [0|1] ""  PC
 SG_ S2P_Bal_CSCSourceVoltFault_62 : 58|1@1+ (1,0) [0|1] ""  PC
 SG_ S2P_Bal_CellVoltOverFault_62 : 59|1@1+ (1,0) [0|1] ""  PC
 SG_ S2P_Bal_CellVoltLowFault_62 : 60|1@1+ (1,0) [0|1] ""  PC
 SG_ S2P_Bal_CSCPCBTempFault_62 : 61|1@1+ (1,0) [0|1] ""  PC
 SG_ S2P_Bal_CSCSourceCurrLowFault_62 : 62|1@1+ (1,0) [0|1] ""  PC
 SG_ S2P_Bal_CSCSourceCurrOvrFault_62 : 63|1@1+ (1,0) [0|1] ""  PC

BO_ 2417487487 S2P_BL_Meg__63: 8 SBMU
 SG_ S2P_Bal_CSCNum_63 : 0|6@1+ (1,0) [0|63] ""  PC
 SG_ S2P_Bal_CellNum_63 : 6|6@1+ (1,0) [0|63] ""  PC
 SG_ S2P_Bal_Type_63 : 12|2@1+ (1,0) [0|3] ""  PC
 SG_ S2P_Bal_TimeRemain_63 : 14|9@1+ (1,0) [0|511] ""  PC
 SG_ S2P_Bal_DeltaVolt_63 : 23|10@1+ (1,0) [0|1023] ""  PC
 SG_ S2P_Bal_CSCPowerCurr_63 : 33|11@1+ (1,0) [0|2047] ""  PC
 SG_ S2P_Bal_TypeLevel_63 : 44|3@1+ (1,0) [0|7] ""  PC
 SG_ S2P_Bal_SystemStatus_63 : 47|2@1+ (1,0) [0|3] ""  PC
 SG_ S2P_Bal_Strategy_63 : 49|1@1+ (1,0) [0|1] ""  PC
 SG_ S2P_Bal_ForceBalMode_63 : 50|2@1+ (1,0) [0|3] ""  PC
 SG_ S2P_Bal_CellTempFault_63 : 52|1@1+ (1,0) [0|1] ""  PC
 SG_ S2P_Bal_CellVoltFail_63 : 53|1@1+ (1,0) [0|1] ""  PC
 SG_ S2P_Bal_CloseBalInstruct_63 : 54|1@1+ (1,0) [0|1] ""  PC
 SG_ S2P_Bal_CCanTimeOut_63 : 55|1@1+ (1,0) [0|1] ""  PC
 SG_ S2P_Bal_CellOffLine_63 : 56|1@1+ (1,0) [0|1] ""  PC
 SG_ S2P_Bal_BalanceCircuitFault_63 : 57|1@1+ (1,0) [0|1] ""  PC
 SG_ S2P_Bal_CSCSourceVoltFault_63 : 58|1@1+ (1,0) [0|1] ""  PC
 SG_ S2P_Bal_CellVoltOverFault_63 : 59|1@1+ (1,0) [0|1] ""  PC
 SG_ S2P_Bal_CellVoltLowFault_63 : 60|1@1+ (1,0) [0|1] ""  PC
 SG_ S2P_Bal_CSCPCBTempFault_63 : 61|1@1+ (1,0) [0|1] ""  PC
 SG_ S2P_Bal_CSCSourceCurrLowFault_63 : 62|1@1+ (1,0) [0|1] ""  PC
 SG_ S2P_Bal_CSCSourceCurrOvrFault_63 : 63|1@1+ (1,0) [0|1] ""  PC

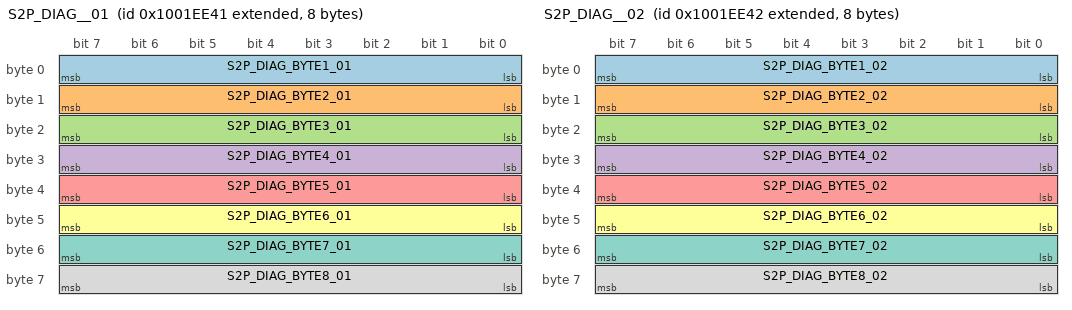
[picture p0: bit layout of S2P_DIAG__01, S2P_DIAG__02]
BO_ 2416045633 S2P_DIAG__01: 8 SBMU
 SG_ S2P_DIAG_BYTE1_01 : 0|8@1+ (1,0) [0|255] ""  PC
 SG_ S2P_DIAG_BYTE2_01 : 8|8@1+ (1,0) [0|255] ""  PC
 SG_ S2P_DIAG_BYTE3_01 : 16|8@1+ (1,0) [0|255] ""  PC
 SG_ S2P_DIAG_BYTE4_01 : 24|8@1+ (1,0) [0|255] ""  PC
 SG_ S2P_DIAG_BYTE5_01 : 32|8@1+ (1,0) [0|255] ""  PC
 SG_ S2P_DIAG_BYTE6_01 : 40|8@1+ (1,0) [0|255] ""  PC
 SG_ S2P_DIAG_BYTE7_01 : 48|8@1+ (1,0) [0|255] ""  PC
 SG_ S2P_DIAG_BYTE8_01 : 56|8@1+ (1,0) [0|255] ""  PC

BO_ 2416045634 S2P_DIAG__02: 8 SBMU
 SG_ S2P_DIAG_BYTE1_02 : 0|8@1+ (1,0) [0|255] ""  PC
 SG_ S2P_DIAG_BYTE2_02 : 8|8@1+ (1,0) [0|255] ""  PC
 SG_ S2P_DIAG_BYTE3_02 : 16|8@1+ (1,0) [0|255] ""  PC
 SG_ S2P_DIAG_BYTE4_02 : 24|8@1+ (1,0) [0|255] ""  PC
 SG_ S2P_DIAG_BYTE5_02 : 32|8@1+ (1,0) [0|255] ""  PC
 SG_ S2P_DIAG_BYTE6_02 : 40|8@1+ (1,0) [0|255] ""  PC
 SG_ S2P_DIAG_BYTE7_02 : 48|8@1+ (1,0) [0|255] ""  PC
 SG_ S2P_DIAG_BYTE8_02 : 56|8@1+ (1,0) [0|255] ""  PC

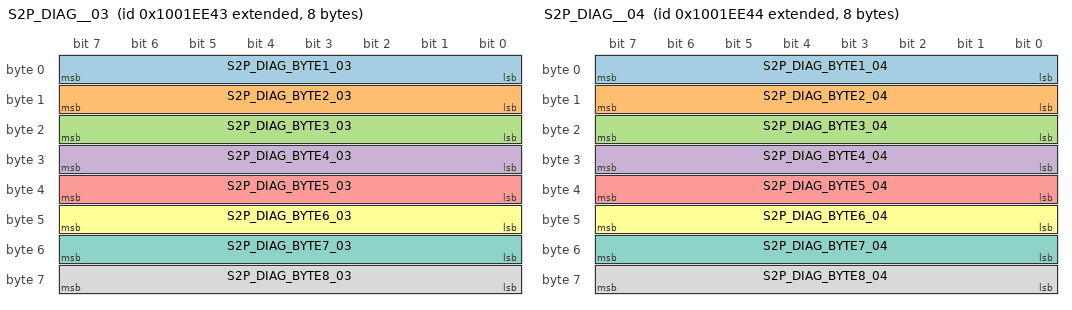
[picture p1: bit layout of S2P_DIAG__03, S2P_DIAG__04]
BO_ 2416045635 S2P_DIAG__03: 8 SBMU
 SG_ S2P_DIAG_BYTE1_03 : 0|8@1+ (1,0) [0|255] ""  PC
 SG_ S2P_DIAG_BYTE2_03 : 8|8@1+ (1,0) [0|255] ""  PC
 SG_ S2P_DIAG_BYTE3_03 : 16|8@1+ (1,0) [0|255] ""  PC
 SG_ S2P_DIAG_BYTE4_03 : 24|8@1+ (1,0) [0|255] ""  PC
 SG_ S2P_DIAG_BYTE5_03 : 32|8@1+ (1,0) [0|255] ""  PC
 SG_ S2P_DIAG_BYTE6_03 : 40|8@1+ (1,0) [0|255] ""  PC
 SG_ S2P_DIAG_BYTE7_03 : 48|8@1+ (1,0) [0|255] ""  PC
 SG_ S2P_DIAG_BYTE8_03 : 56|8@1+ (1,0) [0|255] ""  PC

BO_ 2416045636 S2P_DIAG__04: 8 SBMU
 SG_ S2P_DIAG_BYTE1_04 : 0|8@1+ (1,0) [0|255] ""  PC
 SG_ S2P_DIAG_BYTE2_04 : 8|8@1+ (1,0) [0|255] ""  PC
 SG_ S2P_DIAG_BYTE3_04 : 16|8@1+ (1,0) [0|255] ""  PC
 SG_ S2P_DIAG_BYTE4_04 : 24|8@1+ (1,0) [0|255] ""  PC
 SG_ S2P_DIAG_BYTE5_04 : 32|8@1+ (1,0) [0|255] ""  PC
 SG_ S2P_DIAG_BYTE6_04 : 40|8@1+ (1,0) [0|255] ""  PC
 SG_ S2P_DIAG_BYTE7_04 : 48|8@1+ (1,0) [0|255] ""  PC
 SG_ S2P_DIAG_BYTE8_04 : 56|8@1+ (1,0) [0|255] ""  PC

CM_ SG_ 2417487446 S2P_Bal_CSCNum_22 "CSC号";
CM_ SG_ 2417487446 S2P_Bal_CellNum_22 "CELL号";
CM_ SG_ 2417487446 S2P_Bal_Type_22 "均衡类型";
CM_ SG_ 2417487446 S2P_Bal_TimeRemain_22 "均衡剩余时间";
CM_ SG_ 2417487446 S2P_Bal_DeltaVolt_22 "均衡电芯压差";
CM_ SG_ 2417487446 S2P_Bal_CSCPowerCurr_22 "CSC电源电流";
CM_ SG_ 2417487446 S2P_Bal_TypeLevel_22 "均衡等级";
CM_ SG_ 2417487446 S2P_Bal_SystemStatus_22 "均衡条件判断";
CM_ SG_ 2417487446 S2P_Bal_Strategy_22 "均衡策略";
CM_ SG_ 2417487446 S2P_Bal_ForceBalMode_22 "强制均衡模式";
CM_ SG_ 2417487446 S2P_Bal_CellTempFault_22 "温度单点无效";
CM_ SG_ 2417487446 S2P_Bal_CellVoltFail_22 "电芯电压采样失效";
CM_ SG_ 2417487446 S2P_Bal_CloseBalInstruct_22 "其他模块关闭均衡指令";
CM_ SG_ 2417487446 S2P_Bal_CCanTimeOut_22 "CCAN通讯超时故障";
CM_ SG_ 2417487446 S2P_Bal_CellOffLine_22 "预留";
CM_ SG_ 2417487446 S2P_Bal_BalanceCircuitFault_22 "均衡回路故障";
CM_ SG_ 2417487446 S2P_Bal_CSCSourceVoltFault_22 "CSC供电电压超限";
CM_ SG_ 2417487446 S2P_Bal_CellVoltOverFault_22 "预留";
CM_ SG_ 2417487446 S2P_Bal_CellVoltLowFault_22 "预留";
CM_ SG_ 2417487446 S2P_Bal_CSCPCBTempFault_22 "预留";
CM_ SG_ 2417487446 S2P_Bal_CSCSourceCurrLowFault_22 "CSC供电电流过低，禁止放电均衡";
CM_ SG_ 2417487446 S2P_Bal_CSCSourceCurrOvrFault_22 "CSC供电电流过高，禁止充电均衡";
CM_ SG_ 2417487447 S2P_Bal_CSCNum_23 "CSC号";
CM_ SG_ 2417487447 S2P_Bal_CellNum_23 "CELL号";
CM_ SG_ 2417487447 S2P_Bal_Type_23 "均衡类型";
CM_ SG_ 2417487447 S2P_Bal_TimeRemain_23 "均衡剩余时间";
CM_ SG_ 2417487447 S2P_Bal_DeltaVolt_23 "均衡电芯压差";
CM_ SG_ 2417487447 S2P_Bal_CSCPowerCurr_23 "CSC电源电流";
CM_ SG_ 2417487447 S2P_Bal_TypeLevel_23 "均衡等级";
CM_ SG_ 2417487447 S2P_Bal_SystemStatus_23 "均衡条件判断";
CM_ SG_ 2417487447 S2P_Bal_Strategy_23 "均衡策略";
CM_ SG_ 2417487447 S2P_Bal_ForceBalMode_23 "强制均衡模式";
CM_ SG_ 2417487447 S2P_Bal_CellTempFault_23 "温度单点无效";
CM_ SG_ 2417487447 S2P_Bal_CellVoltFail_23 "电芯电压采样失效";
CM_ SG_ 2417487447 S2P_Bal_CloseBalInstruct_23 "其他模块关闭均衡指令";
CM_ SG_ 2417487447 S2P_Bal_CCanTimeOut_23 "CCAN通讯超时故障";
CM_ SG_ 2417487447 S2P_Bal_CellOffLine_23 "预留";
CM_ SG_ 2417487447 S2P_Bal_BalanceCircuitFault_23 "均衡回路故障";
CM_ SG_ 2417487447 S2P_Bal_CSCSourceVoltFault_23 "CSC供电电压超限";
CM_ SG_ 2417487447 S2P_Bal_CellVoltOverFault_23 "预留";
CM_ SG_ 2417487447 S2P_Bal_CellVoltLowFault_23 "预留";
CM_ SG_ 2417487447 S2P_Bal_CSCPCBTempFault_23 "预留";
CM_ SG_ 2417487447 S2P_Bal_CSCSourceCurrLowFault_23 "CSC供电电流过低，禁止放电均衡";
CM_ SG_ 2417487447 S2P_Bal_CSCSourceCurrOvrFault_23 "CSC供电电流过高，禁止充电均衡";
CM_ SG_ 2417487448 S2P_Bal_CSCNum_24 "CSC号";
CM_ SG_ 2417487448 S2P_Bal_CellNum_24 "CELL号";
CM_ SG_ 2417487448 S2P_Bal_Type_24 "均衡类型";
CM_ SG_ 2417487448 S2P_Bal_TimeRemain_24 "均衡剩余时间";
CM_ SG_ 2417487448 S2P_Bal_DeltaVolt_24 "均衡电芯压差";
CM_ SG_ 2417487448 S2P_Bal_CSCPowerCurr_24 "CSC电源电流";
CM_ SG_ 2417487448 S2P_Bal_TypeLevel_24 "均衡等级";
CM_ SG_ 2417487448 S2P_Bal_SystemStatus_24 "均衡条件判断";
CM_ SG_ 2417487448 S2P_Bal_Strategy_24 "均衡策略";
CM_ SG_ 2417487448 S2P_Bal_ForceBalMode_24 "强制均衡模式";
CM_ SG_ 2417487448 S2P_Bal_CellTempFault_24 "温度单点无效";
CM_ SG_ 2417487448 S2P_Bal_CellVoltFail_24 "电芯电压采样失效";
CM_ SG_ 2417487448 S2P_Bal_CloseBalInstruct_24 "其他模块关闭均衡指令";
CM_ SG_ 2417487448 S2P_Bal_CCanTimeOut_24 "CCAN通讯超时故障";
CM_ SG_ 2417487448 S2P_Bal_CellOffLine_24 "预留";
CM_ SG_ 2417487448 S2P_Bal_BalanceCircuitFault_24 "均衡回路故障";
CM_ SG_ 2417487448 S2P_Bal_CSCSourceVoltFault_24 "CSC供电电压超限";
CM_ SG_ 2417487448 S2P_Bal_CellVoltOverFault_24 "预留";
CM_ SG_ 2417487448 S2P_Bal_CellVoltLowFault_24 "预留";
CM_ SG_ 2417487448 S2P_Bal_CSCPCBTempFault_24 "预留";
CM_ SG_ 2417487448 S2P_Bal_CSCSourceCurrLowFault_24 "CSC供电电流过低，禁止放电均衡";
CM_ SG_ 2417487448 S2P_Bal_CSCSourceCurrOvrFault_24 "CSC供电电流过高，禁止充电均衡";
CM_ SG_ 2417487449 S2P_Bal_CSCNum_25 "CSC号";
CM_ SG_ 2417487449 S2P_Bal_CellNum_25 "CELL号";
CM_ SG_ 2417487449 S2P_Bal_Type_25 "均衡类型";
CM_ SG_ 2417487449 S2P_Bal_TimeRemain_25 "均衡剩余时间";
CM_ SG_ 2417487449 S2P_Bal_DeltaVolt_25 "均衡电芯压差";
CM_ SG_ 2417487449 S2P_Bal_CSCPowerCurr_25 "CSC电源电流";
CM_ SG_ 2417487449 S2P_Bal_TypeLevel_25 "均衡等级";
CM_ SG_ 2417487449 S2P_Bal_SystemStatus_25 "均衡条件判断";
CM_ SG_ 2417487449 S2P_Bal_Strategy_25 "均衡策略";
CM_ SG_ 2417487449 S2P_Bal_ForceBalMode_25 "强制均衡模式";
CM_ SG_ 2417487449 S2P_Bal_CellTempFault_25 "温度单点无效";
CM_ SG_ 2417487449 S2P_Bal_CellVoltFail_25 "电芯电压采样失效";
CM_ SG_ 2417487449 S2P_Bal_CloseBalInstruct_25 "其他模块关闭均衡指令";
CM_ SG_ 2417487449 S2P_Bal_CCanTimeOut_25 "CCAN通讯超时故障";
CM_ SG_ 2417487449 S2P_Bal_CellOffLine_25 "预留";
CM_ SG_ 2417487449 S2P_Bal_BalanceCircuitFault_25 "均衡回路故障";
CM_ SG_ 2417487449 S2P_Bal_CSCSourceVoltFault_25 "CSC供电电压超限";
CM_ SG_ 2417487449 S2P_Bal_CellVoltOverFault_25 "预留";
CM_ SG_ 2417487449 S2P_Bal_CellVoltLowFault_25 "预留";
CM_ SG_ 2417487449 S2P_Bal_CSCPCBTempFault_25 "预留";
CM_ SG_ 2417487449 S2P_Bal_CSCSourceCurrLowFault_25 "CSC供电电流过低，禁止放电均衡";
CM_ SG_ 2417487449 S2P_Bal_CSCSourceCurrOvrFault_25 "CSC供电电流过高，禁止充电均衡";
CM_ SG_ 2417487450 S2P_Bal_CSCNum_26 "CSC号";
CM_ SG_ 2417487450 S2P_Bal_CellNum_26 "CELL号";
CM_ SG_ 2417487450 S2P_Bal_Type_26 "均衡类型";
CM_ SG_ 2417487450 S2P_Bal_TimeRemain_26 "均衡剩余时间";
CM_ SG_ 2417487450 S2P_Bal_DeltaVolt_26 "均衡电芯压差";
CM_ SG_ 2417487450 S2P_Bal_CSCPowerCurr_26 "CSC电源电流";
CM_ SG_ 2417487450 S2P_Bal_TypeLevel_26 "均衡等级";
CM_ SG_ 2417487450 S2P_Bal_SystemStatus_26 "均衡条件判断";
CM_ SG_ 2417487450 S2P_Bal_Strategy_26 "均衡策略";
CM_ SG_ 2417487450 S2P_Bal_ForceBalMode_26 "强制均衡模式";
CM_ SG_ 2417487450 S2P_Bal_CellTempFault_26 "温度单点无效";
CM_ SG_ 2417487450 S2P_Bal_CellVoltFail_26 "电芯电压采样失效";
CM_ SG_ 2417487450 S2P_Bal_CloseBalInstruct_26 "其他模块关闭均衡指令";
CM_ SG_ 2417487450 S2P_Bal_CCanTimeOut_26 "CCAN通讯超时故障";
CM_ SG_ 2417487450 S2P_Bal_CellOffLine_26 "预留";
CM_ SG_ 2417487450 S2P_Bal_BalanceCircuitFault_26 "均衡回路故障";
CM_ SG_ 2417487450 S2P_Bal_CSCSourceVoltFault_26 "CSC供电电压超限";
CM_ SG_ 2417487450 S2P_Bal_CellVoltOverFault_26 "预留";
CM_ SG_ 2417487450 S2P_Bal_CellVoltLowFault_26 "预留";
CM_ SG_ 2417487450 S2P_Bal_CSCPCBTempFault_26 "预留";
CM_ SG_ 2417487450 S2P_Bal_CSCSourceCurrLowFault_26 "CSC供电电流过低，禁止放电均衡";
CM_ SG_ 2417487450 S2P_Bal_CSCSourceCurrOvrFault_26 "CSC供电电流过高，禁止充电均衡";
CM_ SG_ 2417487451 S2P_Bal_CSCNum_27 "CSC号";
CM_ SG_ 2417487451 S2P_Bal_CellNum_27 "CELL号";
CM_ SG_ 2417487451 S2P_Bal_Type_27 "均衡类型";
CM_ SG_ 2417487451 S2P_Bal_TimeRemain_27 "均衡剩余时间";
CM_ SG_ 2417487451 S2P_Bal_DeltaVolt_27 "均衡电芯压差";
CM_ SG_ 2417487451 S2P_Bal_CSCPowerCurr_27 "CSC电源电流";
CM_ SG_ 2417487451 S2P_Bal_TypeLevel_27 "均衡等级";
CM_ SG_ 2417487451 S2P_Bal_SystemStatus_27 "均衡条件判断";
CM_ SG_ 2417487451 S2P_Bal_Strategy_27 "均衡策略";
CM_ SG_ 2417487451 S2P_Bal_ForceBalMode_27 "强制均衡模式";
CM_ SG_ 2417487451 S2P_Bal_CellTempFault_27 "温度单点无效";
CM_ SG_ 2417487451 S2P_Bal_CellVoltFail_27 "电芯电压采样失效";
CM_ SG_ 2417487451 S2P_Bal_CloseBalInstruct_27 "其他模块关闭均衡指令";
CM_ SG_ 2417487451 S2P_Bal_CCanTimeOut_27 "CCAN通讯超时故障";
CM_ SG_ 2417487451 S2P_Bal_CellOffLine_27 "预留";
CM_ SG_ 2417487451 S2P_Bal_BalanceCircuitFault_27 "均衡回路故障";
CM_ SG_ 2417487451 S2P_Bal_CSCSourceVoltFault_27 "CSC供电电压超限";
CM_ SG_ 2417487451 S2P_Bal_CellVoltOverFault_27 "预留";
CM_ SG_ 2417487451 S2P_Bal_CellVoltLowFault_27 "预留";
CM_ SG_ 2417487451 S2P_Bal_CSCPCBTempFault_27 "预留";
CM_ SG_ 2417487451 S2P_Bal_CSCSourceCurrLowFault_27 "CSC供电电流过低，禁止放电均衡";
CM_ SG_ 2417487451 S2P_Bal_CSCSourceCurrOvrFault_27 "CSC供电电流过高，禁止充电均衡";
CM_ SG_ 2417487452 S2P_Bal_CSCNum_28 "CSC号";
CM_ SG_ 2417487452 S2P_Bal_CellNum_28 "CELL号";
CM_ SG_ 2417487452 S2P_Bal_Type_28 "均衡类型";
CM_ SG_ 2417487452 S2P_Bal_TimeRemain_28 "均衡剩余时间";
CM_ SG_ 2417487452 S2P_Bal_DeltaVolt_28 "均衡电芯压差";
CM_ SG_ 2417487452 S2P_Bal_CSCPowerCurr_28 "CSC电源电流";
CM_ SG_ 2417487452 S2P_Bal_TypeLevel_28 "均衡等级";
CM_ SG_ 2417487452 S2P_Bal_SystemStatus_28 "均衡条件判断";
CM_ SG_ 2417487452 S2P_Bal_Strategy_28 "均衡策略";
CM_ SG_ 2417487452 S2P_Bal_ForceBalMode_28 "强制均衡模式";
CM_ SG_ 2417487452 S2P_Bal_CellTempFault_28 "温度单点无效";
CM_ SG_ 2417487452 S2P_Bal_CellVoltFail_28 "电芯电压采样失效";
CM_ SG_ 2417487452 S2P_Bal_CloseBalInstruct_28 "其他模块关闭均衡指令";
CM_ SG_ 2417487452 S2P_Bal_CCanTimeOut_28 "CCAN通讯超时故障";
CM_ SG_ 2417487452 S2P_Bal_CellOffLine_28 "预留";
CM_ SG_ 2417487452 S2P_Bal_BalanceCircuitFault_28 "均衡回路故障";
CM_ SG_ 2417487452 S2P_Bal_CSCSourceVoltFault_28 "CSC供电电压超限";
CM_ SG_ 2417487452 S2P_Bal_CellVoltOverFault_28 "预留";
CM_ SG_ 2417487452 S2P_Bal_CellVoltLowFault_28 "预留";
CM_ SG_ 2417487452 S2P_Bal_CSCPCBTempFault_28 "预留";
CM_ SG_ 2417487452 S2P_Bal_CSCSourceCurrLowFault_28 "CSC供电电流过低，禁止放电均衡";
CM_ SG_ 2417487452 S2P_Bal_CSCSourceCurrOvrFault_28 "CSC供电电流过高，禁止充电均衡";
CM_ SG_ 2417487453 S2P_Bal_CSCNum_29 "CSC号";
CM_ SG_ 2417487453 S2P_Bal_CellNum_29 "CELL号";
CM_ SG_ 2417487453 S2P_Bal_Type_29 "均衡类型";
CM_ SG_ 2417487453 S2P_Bal_TimeRemain_29 "均衡剩余时间";
CM_ SG_ 2417487453 S2P_Bal_DeltaVolt_29 "均衡电芯压差";
CM_ SG_ 2417487453 S2P_Bal_CSCPowerCurr_29 "CSC电源电流";
CM_ SG_ 2417487453 S2P_Bal_TypeLevel_29 "均衡等级";
CM_ SG_ 2417487453 S2P_Bal_SystemStatus_29 "均衡条件判断";
CM_ SG_ 2417487453 S2P_Bal_Strategy_29 "均衡策略";
CM_ SG_ 2417487453 S2P_Bal_ForceBalMode_29 "强制均衡模式";
CM_ SG_ 2417487453 S2P_Bal_CellTempFault_29 "温度单点无效";
CM_ SG_ 2417487453 S2P_Bal_CellVoltFail_29 "电芯电压采样失效";
CM_ SG_ 2417487453 S2P_Bal_CloseBalInstruct_29 "其他模块关闭均衡指令";
CM_ SG_ 2417487453 S2P_Bal_CCanTimeOut_29 "CCAN通讯超时故障";
CM_ SG_ 2417487453 S2P_Bal_CellOffLine_29 "预留";
CM_ SG_ 2417487453 S2P_Bal_BalanceCircuitFault_29 "均衡回路故障";
CM_ SG_ 2417487453 S2P_Bal_CSCSourceVoltFault_29 "CSC供电电压超限";
CM_ SG_ 2417487453 S2P_Bal_CellVoltOverFault_29 "预留";
CM_ SG_ 2417487453 S2P_Bal_CellVoltLowFault_29 "预留";
CM_ SG_ 2417487453 S2P_Bal_CSCPCBTempFault_29 "预留";
CM_ SG_ 2417487453 S2P_Bal_CSCSourceCurrLowFault_29 "CSC供电电流过低，禁止放电均衡";
CM_ SG_ 2417487453 S2P_Bal_CSCSourceCurrOvrFault_29 "CSC供电电流过高，禁止充电均衡";
CM_ SG_ 2417487454 S2P_Bal_CSCNum_30 "CSC号";
CM_ SG_ 2417487454 S2P_Bal_CellNum_30 "CELL号";
CM_ SG_ 2417487454 S2P_Bal_Type_30 "均衡类型";
CM_ SG_ 2417487454 S2P_Bal_TimeRemain_30 "均衡剩余时间";
CM_ SG_ 2417487454 S2P_Bal_DeltaVolt_30 "均衡电芯压差";
CM_ SG_ 2417487454 S2P_Bal_CSCPowerCurr_30 "CSC电源电流";
CM_ SG_ 2417487454 S2P_Bal_TypeLevel_30 "均衡等级";
CM_ SG_ 2417487454 S2P_Bal_SystemStatus_30 "均衡条件判断";
CM_ SG_ 2417487454 S2P_Bal_Strategy_30 "均衡策略";
CM_ SG_ 2417487454 S2P_Bal_ForceBalMode_30 "强制均衡模式";
CM_ SG_ 2417487454 S2P_Bal_CellTempFault_30 "温度单点无效";
CM_ SG_ 2417487454 S2P_Bal_CellVoltFail_30 "电芯电压采样失效";
CM_ SG_ 2417487454 S2P_Bal_CloseBalInstruct_30 "其他模块关闭均衡指令";
CM_ SG_ 2417487454 S2P_Bal_CCanTimeOut_30 "CCAN通讯超时故障";
CM_ SG_ 2417487454 S2P_Bal_CellOffLine_30 "预留";
CM_ SG_ 2417487454 S2P_Bal_BalanceCircuitFault_30 "均衡回路故障";
CM_ SG_ 2417487454 S2P_Bal_CSCSourceVoltFault_30 "CSC供电电压超限";
CM_ SG_ 2417487454 S2P_Bal_CellVoltOverFault_30 "预留";
CM_ SG_ 2417487454 S2P_Bal_CellVoltLowFault_30 "预留";
CM_ SG_ 2417487454 S2P_Bal_CSCPCBTempFault_30 "预留";
CM_ SG_ 2417487454 S2P_Bal_CSCSourceCurrLowFault_30 "CSC供电电流过低，禁止放电均衡";
CM_ SG_ 2417487454 S2P_Bal_CSCSourceCurrOvrFault_30 "CSC供电电流过高，禁止充电均衡";
CM_ SG_ 2417487455 S2P_Bal_CSCNum_31 "CSC号";
CM_ SG_ 2417487455 S2P_Bal_CellNum_31 "CELL号";
CM_ SG_ 2417487455 S2P_Bal_Type_31 "均衡类型";
CM_ SG_ 2417487455 S2P_Bal_TimeRemain_31 "均衡剩余时间";
CM_ SG_ 2417487455 S2P_Bal_DeltaVolt_31 "均衡电芯压差";
CM_ SG_ 2417487455 S2P_Bal_CSCPowerCurr_31 "CSC电源电流";
CM_ SG_ 2417487455 S2P_Bal_TypeLevel_31 "均衡等级";
CM_ SG_ 2417487455 S2P_Bal_SystemStatus_31 "均衡条件判断";
CM_ SG_ 2417487455 S2P_Bal_Strategy_31 "均衡策略";
CM_ SG_ 2417487455 S2P_Bal_ForceBalMode_31 "强制均衡模式";
CM_ SG_ 2417487455 S2P_Bal_CellTempFault_31 "温度单点无效";
CM_ SG_ 2417487455 S2P_Bal_CellVoltFail_31 "电芯电压采样失效";
CM_ SG_ 2417487455 S2P_Bal_CloseBalInstruct_31 "其他模块关闭均衡指令";
CM_ SG_ 2417487455 S2P_Bal_CCanTimeOut_31 "CCAN通讯超时故障";
CM_ SG_ 2417487455 S2P_Bal_CellOffLine_31 "预留";
CM_ SG_ 2417487455 S2P_Bal_BalanceCircuitFault_31 "均衡回路故障";
CM_ SG_ 2417487455 S2P_Bal_CSCSourceVoltFault_31 "CSC供电电压超限";
CM_ SG_ 2417487455 S2P_Bal_CellVoltOverFault_31 "预留";
CM_ SG_ 2417487455 S2P_Bal_CellVoltLowFault_31 "预留";
CM_ SG_ 2417487455 S2P_Bal_CSCPCBTempFault_31 "预留";
CM_ SG_ 2417487455 S2P_Bal_CSCSourceCurrLowFault_31 "CSC供电电流过低，禁止放电均衡";
CM_ SG_ 2417487455 S2P_Bal_CSCSourceCurrOvrFault_31 "CSC供电电流过高，禁止充电均衡";
CM_ SG_ 2417487456 S2P_Bal_CSCNum_32 "CSC号";
CM_ SG_ 2417487456 S2P_Bal_CellNum_32 "CELL号";
CM_ SG_ 2417487456 S2P_Bal_Type_32 "均衡类型";
CM_ SG_ 2417487456 S2P_Bal_TimeRemain_32 "均衡剩余时间";
CM_ SG_ 2417487456 S2P_Bal_DeltaVolt_32 "均衡电芯压差";
CM_ SG_ 2417487456 S2P_Bal_CSCPowerCurr_32 "CSC电源电流";
CM_ SG_ 2417487456 S2P_Bal_TypeLevel_32 "均衡等级";
CM_ SG_ 2417487456 S2P_Bal_SystemStatus_32 "均衡条件判断";
CM_ SG_ 2417487456 S2P_Bal_Strategy_32 "均衡策略";
CM_ SG_ 2417487456 S2P_Bal_ForceBalMode_32 "强制均衡模式";
CM_ SG_ 2417487456 S2P_Bal_CellTempFault_32 "温度单点无效";
CM_ SG_ 2417487456 S2P_Bal_CellVoltFail_32 "电芯电压采样失效";
CM_ SG_ 2417487456 S2P_Bal_CloseBalInstruct_32 "其他模块关闭均衡指令";
CM_ SG_ 2417487456 S2P_Bal_CCanTimeOut_32 "CCAN通讯超时故障";
CM_ SG_ 2417487456 S2P_Bal_CellOffLine_32 "预留";
CM_ SG_ 2417487456 S2P_Bal_BalanceCircuitFault_32 "均衡回路故障";
CM_ SG_ 2417487456 S2P_Bal_CSCSourceVoltFault_32 "CSC供电电压超限";
CM_ SG_ 2417487456 S2P_Bal_CellVoltOverFault_32 "预留";
CM_ SG_ 2417487456 S2P_Bal_CellVoltLowFault_32 "预留";
CM_ SG_ 2417487456 S2P_Bal_CSCPCBTempFault_32 "预留";
CM_ SG_ 2417487456 S2P_Bal_CSCSourceCurrLowFault_32 "CSC供电电流过低，禁止放电均衡";
CM_ SG_ 2417487456 S2P_Bal_CSCSourceCurrOvrFault_32 "CSC供电电流过高，禁止充电均衡";
CM_ SG_ 2417487457 S2P_Bal_CSCNum_33 "CSC号";
CM_ SG_ 2417487457 S2P_Bal_CellNum_33 "CELL号";
CM_ SG_ 2417487457 S2P_Bal_Type_33 "均衡类型";
CM_ SG_ 2417487457 S2P_Bal_TimeRemain_33 "均衡剩余时间";
CM_ SG_ 2417487457 S2P_Bal_DeltaVolt_33 "均衡电芯压差";
CM_ SG_ 2417487457 S2P_Bal_CSCPowerCurr_33 "CSC电源电流";
CM_ SG_ 2417487457 S2P_Bal_TypeLevel_33 "均衡等级";
CM_ SG_ 2417487457 S2P_Bal_SystemStatus_33 "均衡条件判断";
CM_ SG_ 2417487457 S2P_Bal_Strategy_33 "均衡策略";
CM_ SG_ 2417487457 S2P_Bal_ForceBalMode_33 "强制均衡模式";
CM_ SG_ 2417487457 S2P_Bal_CellTempFault_33 "温度单点无效";
CM_ SG_ 2417487457 S2P_Bal_CellVoltFail_33 "电芯电压采样失效";
CM_ SG_ 2417487457 S2P_Bal_CloseBalInstruct_33 "其他模块关闭均衡指令";
CM_ SG_ 2417487457 S2P_Bal_CCanTimeOut_33 "CCAN通讯超时故障";
CM_ SG_ 2417487457 S2P_Bal_CellOffLine_33 "预留";
CM_ SG_ 2417487457 S2P_Bal_BalanceCircuitFault_33 "均衡回路故障";
CM_ SG_ 2417487457 S2P_Bal_CSCSourceVoltFault_33 "CSC供电电压超限";
CM_ SG_ 2417487457 S2P_Bal_CellVoltOverFault_33 "预留";
CM_ SG_ 2417487457 S2P_Bal_CellVoltLowFault_33 "预留";
CM_ SG_ 2417487457 S2P_Bal_CSCPCBTempFault_33 "预留";
CM_ SG_ 2417487457 S2P_Bal_CSCSourceCurrLowFault_33 "CSC供电电流过低，禁止放电均衡";
CM_ SG_ 2417487457 S2P_Bal_CSCSourceCurrOvrFault_33 "CSC供电电流过高，禁止充电均衡";
CM_ SG_ 2417487458 S2P_Bal_CSCNum_34 "CSC号";
CM_ SG_ 2417487458 S2P_Bal_CellNum_34 "CELL号";
CM_ SG_ 2417487458 S2P_Bal_Type_34 "均衡类型";
CM_ SG_ 2417487458 S2P_Bal_TimeRemain_34 "均衡剩余时间";
CM_ SG_ 2417487458 S2P_Bal_DeltaVolt_34 "均衡电芯压差";
CM_ SG_ 2417487458 S2P_Bal_CSCPowerCurr_34 "CSC电源电流";
CM_ SG_ 2417487458 S2P_Bal_TypeLevel_34 "均衡等级";
CM_ SG_ 2417487458 S2P_Bal_SystemStatus_34 "均衡条件判断";
CM_ SG_ 2417487458 S2P_Bal_Strategy_34 "均衡策略";
CM_ SG_ 2417487458 S2P_Bal_ForceBalMode_34 "强制均衡模式";
CM_ SG_ 2417487458 S2P_Bal_CellTempFault_34 "温度单点无效";
CM_ SG_ 2417487458 S2P_Bal_CellVoltFail_34 "电芯电压采样失效";
CM_ SG_ 2417487458 S2P_Bal_CloseBalInstruct_34 "其他模块关闭均衡指令";
CM_ SG_ 2417487458 S2P_Bal_CCanTimeOut_34 "CCAN通讯超时故障";
CM_ SG_ 2417487458 S2P_Bal_CellOffLine_34 "预留";
CM_ SG_ 2417487458 S2P_Bal_BalanceCircuitFault_34 "均衡回路故障";
CM_ SG_ 2417487458 S2P_Bal_CSCSourceVoltFault_34 "CSC供电电压超限";
CM_ SG_ 2417487458 S2P_Bal_CellVoltOverFault_34 "预留";
CM_ SG_ 2417487458 S2P_Bal_CellVoltLowFault_34 "预留";
CM_ SG_ 2417487458 S2P_Bal_CSCPCBTempFault_34 "预留";
CM_ SG_ 2417487458 S2P_Bal_CSCSourceCurrLowFault_34 "CSC供电电流过低，禁止放电均衡";
CM_ SG_ 2417487458 S2P_Bal_CSCSourceCurrOvrFault_34 "CSC供电电流过高，禁止充电均衡";
CM_ SG_ 2417487459 S2P_Bal_CSCNum_35 "CSC号";
CM_ SG_ 2417487459 S2P_Bal_CellNum_35 "CELL号";
CM_ SG_ 2417487459 S2P_Bal_Type_35 "均衡类型";
CM_ SG_ 2417487459 S2P_Bal_TimeRemain_35 "均衡剩余时间";
CM_ SG_ 2417487459 S2P_Bal_DeltaVolt_35 "均衡电芯压差";
CM_ SG_ 2417487459 S2P_Bal_CSCPowerCurr_35 "CSC电源电流";
CM_ SG_ 2417487459 S2P_Bal_TypeLevel_35 "均衡等级";
CM_ SG_ 2417487459 S2P_Bal_SystemStatus_35 "均衡条件判断";
CM_ SG_ 2417487459 S2P_Bal_Strategy_35 "均衡策略";
CM_ SG_ 2417487459 S2P_Bal_ForceBalMode_35 "强制均衡模式";
CM_ SG_ 2417487459 S2P_Bal_CellTempFault_35 "温度单点无效";
CM_ SG_ 2417487459 S2P_Bal_CellVoltFail_35 "电芯电压采样失效";
CM_ SG_ 2417487459 S2P_Bal_CloseBalInstruct_35 "其他模块关闭均衡指令";
CM_ SG_ 2417487459 S2P_Bal_CCanTimeOut_35 "CCAN通讯超时故障";
CM_ SG_ 2417487459 S2P_Bal_CellOffLine_35 "预留";
CM_ SG_ 2417487459 S2P_Bal_BalanceCircuitFault_35 "均衡回路故障";
CM_ SG_ 2417487459 S2P_Bal_CSCSourceVoltFault_35 "CSC供电电压超限";
CM_ SG_ 2417487459 S2P_Bal_CellVoltOverFault_35 "预留";
CM_ SG_ 2417487459 S2P_Bal_CellVoltLowFault_35 "预留";
CM_ SG_ 2417487459 S2P_Bal_CSCPCBTempFault_35 "预留";
CM_ SG_ 2417487459 S2P_Bal_CSCSourceCurrLowFault_35 "CSC供电电流过低，禁止放电均衡";
CM_ SG_ 2417487459 S2P_Bal_CSCSourceCurrOvrFault_35 "CSC供电电流过高，禁止充电均衡";
CM_ SG_ 2417487460 S2P_Bal_CSCNum_36 "CSC号";
CM_ SG_ 2417487460 S2P_Bal_CellNum_36 "CELL号";
CM_ SG_ 2417487460 S2P_Bal_Type_36 "均衡类型";
CM_ SG_ 2417487460 S2P_Bal_TimeRemain_36 "均衡剩余时间";
CM_ SG_ 2417487460 S2P_Bal_DeltaVolt_36 "均衡电芯压差";
CM_ SG_ 2417487460 S2P_Bal_CSCPowerCurr_36 "CSC电源电流";
CM_ SG_ 2417487460 S2P_Bal_TypeLevel_36 "均衡等级";
CM_ SG_ 2417487460 S2P_Bal_SystemStatus_36 "均衡条件判断";
CM_ SG_ 2417487460 S2P_Bal_Strategy_36 "均衡策略";
CM_ SG_ 2417487460 S2P_Bal_ForceBalMode_36 "强制均衡模式";
CM_ SG_ 2417487460 S2P_Bal_CellTempFault_36 "温度单点无效";
CM_ SG_ 2417487460 S2P_Bal_CellVoltFail_36 "电芯电压采样失效";
CM_ SG_ 2417487460 S2P_Bal_CloseBalInstruct_36 "其他模块关闭均衡指令";
CM_ SG_ 2417487460 S2P_Bal_CCanTimeOut_36 "CCAN通讯超时故障";
CM_ SG_ 2417487460 S2P_Bal_CellOffLine_36 "预留";
CM_ SG_ 2417487460 S2P_Bal_BalanceCircuitFault_36 "均衡回路故障";
CM_ SG_ 2417487460 S2P_Bal_CSCSourceVoltFault_36 "CSC供电电压超限";
CM_ SG_ 2417487460 S2P_Bal_CellVoltOverFault_36 "预留";
CM_ SG_ 2417487460 S2P_Bal_CellVoltLowFault_36 "预留";
CM_ SG_ 2417487460 S2P_Bal_CSCPCBTempFault_36 "预留";
CM_ SG_ 2417487460 S2P_Bal_CSCSourceCurrLowFault_36 "CSC供电电流过低，禁止放电均衡";
CM_ SG_ 2417487460 S2P_Bal_CSCSourceCurrOvrFault_36 "CSC供电电流过高，禁止充电均衡";
CM_ SG_ 2417487461 S2P_Bal_CSCNum_37 "CSC号";
CM_ SG_ 2417487461 S2P_Bal_CellNum_37 "CELL号";
CM_ SG_ 2417487461 S2P_Bal_Type_37 "均衡类型";
CM_ SG_ 2417487461 S2P_Bal_TimeRemain_37 "均衡剩余时间";
CM_ SG_ 2417487461 S2P_Bal_DeltaVolt_37 "均衡电芯压差";
CM_ SG_ 2417487461 S2P_Bal_CSCPowerCurr_37 "CSC电源电流";
CM_ SG_ 2417487461 S2P_Bal_TypeLevel_37 "均衡等级";
CM_ SG_ 2417487461 S2P_Bal_SystemStatus_37 "均衡条件判断";
CM_ SG_ 2417487461 S2P_Bal_Strategy_37 "均衡策略";
CM_ SG_ 2417487461 S2P_Bal_ForceBalMode_37 "强制均衡模式";
CM_ SG_ 2417487461 S2P_Bal_CellTempFault_37 "温度单点无效";
CM_ SG_ 2417487461 S2P_Bal_CellVoltFail_37 "电芯电压采样失效";
CM_ SG_ 2417487461 S2P_Bal_CloseBalInstruct_37 "其他模块关闭均衡指令";
CM_ SG_ 2417487461 S2P_Bal_CCanTimeOut_37 "CCAN通讯超时故障";
CM_ SG_ 2417487461 S2P_Bal_CellOffLine_37 "预留";
CM_ SG_ 2417487461 S2P_Bal_BalanceCircuitFault_37 "均衡回路故障";
CM_ SG_ 2417487461 S2P_Bal_CSCSourceVoltFault_37 "CSC供电电压超限";
CM_ SG_ 2417487461 S2P_Bal_CellVoltOverFault_37 "预留";
CM_ SG_ 2417487461 S2P_Bal_CellVoltLowFault_37 "预留";
CM_ SG_ 2417487461 S2P_Bal_CSCPCBTempFault_37 "预留";
CM_ SG_ 2417487461 S2P_Bal_CSCSourceCurrLowFault_37 "CSC供电电流过低，禁止放电均衡";
CM_ SG_ 2417487461 S2P_Bal_CSCSourceCurrOvrFault_37 "CSC供电电流过高，禁止充电均衡";
CM_ SG_ 2417487462 S2P_Bal_CSCNum_38 "CSC号";
CM_ SG_ 2417487462 S2P_Bal_CellNum_38 "CELL号";
CM_ SG_ 2417487462 S2P_Bal_Type_38 "均衡类型";
CM_ SG_ 2417487462 S2P_Bal_TimeRemain_38 "均衡剩余时间";
CM_ SG_ 2417487462 S2P_Bal_DeltaVolt_38 "均衡电芯压差";
CM_ SG_ 2417487462 S2P_Bal_CSCPowerCurr_38 "CSC电源电流";
CM_ SG_ 2417487462 S2P_Bal_TypeLevel_38 "均衡等级";
CM_ SG_ 2417487462 S2P_Bal_SystemStatus_38 "均衡条件判断";
CM_ SG_ 2417487462 S2P_Bal_Strategy_38 "均衡策略";
CM_ SG_ 2417487462 S2P_Bal_ForceBalMode_38 "强制均衡模式";
CM_ SG_ 2417487462 S2P_Bal_CellTempFault_38 "温度单点无效";
CM_ SG_ 2417487462 S2P_Bal_CellVoltFail_38 "电芯电压采样失效";
CM_ SG_ 2417487462 S2P_Bal_CloseBalInstruct_38 "其他模块关闭均衡指令";
CM_ SG_ 2417487462 S2P_Bal_CCanTimeOut_38 "CCAN通讯超时故障";
CM_ SG_ 2417487462 S2P_Bal_CellOffLine_38 "预留";
CM_ SG_ 2417487462 S2P_Bal_BalanceCircuitFault_38 "均衡回路故障";
CM_ SG_ 2417487462 S2P_Bal_CSCSourceVoltFault_38 "CSC供电电压超限";
CM_ SG_ 2417487462 S2P_Bal_CellVoltOverFault_38 "预留";
CM_ SG_ 2417487462 S2P_Bal_CellVoltLowFault_38 "预留";
CM_ SG_ 2417487462 S2P_Bal_CSCPCBTempFault_38 "预留";
CM_ SG_ 2417487462 S2P_Bal_CSCSourceCurrLowFault_38 "CSC供电电流过低，禁止放电均衡";
CM_ SG_ 2417487462 S2P_Bal_CSCSourceCurrOvrFault_38 "CSC供电电流过高，禁止充电均衡";
CM_ SG_ 2417487463 S2P_Bal_CSCNum_39 "CSC号";
CM_ SG_ 2417487463 S2P_Bal_CellNum_39 "CELL号";
CM_ SG_ 2417487463 S2P_Bal_Type_39 "均衡类型";
CM_ SG_ 2417487463 S2P_Bal_TimeRemain_39 "均衡剩余时间";
CM_ SG_ 2417487463 S2P_Bal_DeltaVolt_39 "均衡电芯压差";
CM_ SG_ 2417487463 S2P_Bal_CSCPowerCurr_39 "CSC电源电流";
CM_ SG_ 2417487463 S2P_Bal_TypeLevel_39 "均衡等级";
CM_ SG_ 2417487463 S2P_Bal_SystemStatus_39 "均衡条件判断";
CM_ SG_ 2417487463 S2P_Bal_Strategy_39 "均衡策略";
CM_ SG_ 2417487463 S2P_Bal_ForceBalMode_39 "强制均衡模式";
CM_ SG_ 2417487463 S2P_Bal_CellTempFault_39 "温度单点无效";
CM_ SG_ 2417487463 S2P_Bal_CellVoltFail_39 "电芯电压采样失效";
CM_ SG_ 2417487463 S2P_Bal_CloseBalInstruct_39 "其他模块关闭均衡指令";
CM_ SG_ 2417487463 S2P_Bal_CCanTimeOut_39 "CCAN通讯超时故障";
CM_ SG_ 2417487463 S2P_Bal_CellOffLine_39 "预留";
CM_ SG_ 2417487463 S2P_Bal_BalanceCircuitFault_39 "均衡回路故障";
CM_ SG_ 2417487463 S2P_Bal_CSCSourceVoltFault_39 "CSC供电电压超限";
CM_ SG_ 2417487463 S2P_Bal_CellVoltOverFault_39 "预留";
CM_ SG_ 2417487463 S2P_Bal_CellVoltLowFault_39 "预留";
CM_ SG_ 2417487463 S2P_Bal_CSCPCBTempFault_39 "预留";
CM_ SG_ 2417487463 S2P_Bal_CSCSourceCurrLowFault_39 "CSC供电电流过低，禁止放电均衡";
CM_ SG_ 2417487463 S2P_Bal_CSCSourceCurrOvrFault_39 "CSC供电电流过高，禁止充电均衡";
CM_ SG_ 2417487464 S2P_Bal_CSCNum_40 "CSC号";
CM_ SG_ 2417487464 S2P_Bal_CellNum_40 "CELL号";
CM_ SG_ 2417487464 S2P_Bal_Type_40 "均衡类型";
CM_ SG_ 2417487464 S2P_Bal_TimeRemain_40 "均衡剩余时间";
CM_ SG_ 2417487464 S2P_Bal_DeltaVolt_40 "均衡电芯压差";
CM_ SG_ 2417487464 S2P_Bal_CSCPowerCurr_40 "CSC电源电流";
CM_ SG_ 2417487464 S2P_Bal_TypeLevel_40 "均衡等级";
CM_ SG_ 2417487464 S2P_Bal_SystemStatus_40 "均衡条件判断";
CM_ SG_ 2417487464 S2P_Bal_Strategy_40 "均衡策略";
CM_ SG_ 2417487464 S2P_Bal_ForceBalMode_40 "强制均衡模式";
CM_ SG_ 2417487464 S2P_Bal_CellTempFault_40 "温度单点无效";
CM_ SG_ 2417487464 S2P_Bal_CellVoltFail_40 "电芯电压采样失效";
CM_ SG_ 2417487464 S2P_Bal_CloseBalInstruct_40 "其他模块关闭均衡指令";
CM_ SG_ 2417487464 S2P_Bal_CCanTimeOut_40 "CCAN通讯超时故障";
CM_ SG_ 2417487464 S2P_Bal_CellOffLine_40 "预留";
CM_ SG_ 2417487464 S2P_Bal_BalanceCircuitFault_40 "均衡回路故障";
CM_ SG_ 2417487464 S2P_Bal_CSCSourceVoltFault_40 "CSC供电电压超限";
CM_ SG_ 2417487464 S2P_Bal_CellVoltOverFault_40 "预留";
CM_ SG_ 2417487464 S2P_Bal_CellVoltLowFault_40 "预留";
CM_ SG_ 2417487464 S2P_Bal_CSCPCBTempFault_40 "预留";
CM_ SG_ 2417487464 S2P_Bal_CSCSourceCurrLowFault_40 "CSC供电电流过低，禁止放电均衡";
CM_ SG_ 2417487464 S2P_Bal_CSCSourceCurrOvrFault_40 "CSC供电电流过高，禁止充电均衡";
CM_ SG_ 2417487465 S2P_Bal_CSCNum_41 "CSC号";
CM_ SG_ 2417487465 S2P_Bal_CellNum_41 "CELL号";
CM_ SG_ 2417487465 S2P_Bal_Type_41 "均衡类型";
CM_ SG_ 2417487465 S2P_Bal_TimeRemain_41 "均衡剩余时间";
CM_ SG_ 2417487465 S2P_Bal_DeltaVolt_41 "均衡电芯压差";
CM_ SG_ 2417487465 S2P_Bal_CSCPowerCurr_41 "CSC电源电流";
CM_ SG_ 2417487465 S2P_Bal_TypeLevel_41 "均衡等级";
CM_ SG_ 2417487465 S2P_Bal_SystemStatus_41 "均衡条件判断";
CM_ SG_ 2417487465 S2P_Bal_Strategy_41 "均衡策略";
CM_ SG_ 2417487465 S2P_Bal_ForceBalMode_41 "强制均衡模式";
CM_ SG_ 2417487465 S2P_Bal_CellTempFault_41 "温度单点无效";
CM_ SG_ 2417487465 S2P_Bal_CellVoltFail_41 "电芯电压采样失效";
CM_ SG_ 2417487465 S2P_Bal_CloseBalInstruct_41 "其他模块关闭均衡指令";
CM_ SG_ 2417487465 S2P_Bal_CCanTimeOut_41 "CCAN通讯超时故障";
CM_ SG_ 2417487465 S2P_Bal_CellOffLine_41 "预留";
CM_ SG_ 2417487465 S2P_Bal_BalanceCircuitFault_41 "均衡回路故障";
CM_ SG_ 2417487465 S2P_Bal_CSCSourceVoltFault_41 "CSC供电电压超限";
CM_ SG_ 2417487465 S2P_Bal_CellVoltOverFault_41 "预留";
CM_ SG_ 2417487465 S2P_Bal_CellVoltLowFault_41 "预留";
CM_ SG_ 2417487465 S2P_Bal_CSCPCBTempFault_41 "预留";
CM_ SG_ 2417487465 S2P_Bal_CSCSourceCurrLowFault_41 "CSC供电电流过低，禁止放电均衡";
CM_ SG_ 2417487465 S2P_Bal_CSCSourceCurrOvrFault_41 "CSC供电电流过高，禁止充电均衡";
CM_ SG_ 2417487466 S2P_Bal_CSCNum_42 "CSC号";
CM_ SG_ 2417487466 S2P_Bal_CellNum_42 "CELL号";
CM_ SG_ 2417487466 S2P_Bal_Type_42 "均衡类型";
CM_ SG_ 2417487466 S2P_Bal_TimeRemain_42 "均衡剩余时间";
CM_ SG_ 2417487466 S2P_Bal_DeltaVolt_42 "均衡电芯压差";
CM_ SG_ 2417487466 S2P_Bal_CSCPowerCurr_42 "CSC电源电流";
CM_ SG_ 2417487466 S2P_Bal_TypeLevel_42 "均衡等级";
CM_ SG_ 2417487466 S2P_Bal_SystemStatus_42 "均衡条件判断";
CM_ SG_ 2417487466 S2P_Bal_Strategy_42 "均衡策略";
CM_ SG_ 2417487466 S2P_Bal_ForceBalMode_42 "强制均衡模式";
CM_ SG_ 2417487466 S2P_Bal_CellTempFault_42 "温度单点无效";
CM_ SG_ 2417487466 S2P_Bal_CellVoltFail_42 "电芯电压采样失效";
CM_ SG_ 2417487466 S2P_Bal_CloseBalInstruct_42 "其他模块关闭均衡指令";
CM_ SG_ 2417487466 S2P_Bal_CCanTimeOut_42 "CCAN通讯超时故障";
CM_ SG_ 2417487466 S2P_Bal_CellOffLine_42 "预留";
CM_ SG_ 2417487466 S2P_Bal_BalanceCircuitFault_42 "均衡回路故障";
CM_ SG_ 2417487466 S2P_Bal_CSCSourceVoltFault_42 "CSC供电电压超限";
CM_ SG_ 2417487466 S2P_Bal_CellVoltOverFault_42 "预留";
CM_ SG_ 2417487466 S2P_Bal_CellVoltLowFault_42 "预留";
CM_ SG_ 2417487466 S2P_Bal_CSCPCBTempFault_42 "预留";
CM_ SG_ 2417487466 S2P_Bal_CSCSourceCurrLowFault_42 "CSC供电电流过低，禁止放电均衡";
CM_ SG_ 2417487466 S2P_Bal_CSCSourceCurrOvrFault_42 "CSC供电电流过高，禁止充电均衡";
CM_ SG_ 2417487467 S2P_Bal_CSCNum_43 "CSC号";
CM_ SG_ 2417487467 S2P_Bal_CellNum_43 "CELL号";
CM_ SG_ 2417487467 S2P_Bal_Type_43 "均衡类型";
CM_ SG_ 2417487467 S2P_Bal_TimeRemain_43 "均衡剩余时间";
CM_ SG_ 2417487467 S2P_Bal_DeltaVolt_43 "均衡电芯压差";
CM_ SG_ 2417487467 S2P_Bal_CSCPowerCurr_43 "CSC电源电流";
CM_ SG_ 2417487467 S2P_Bal_TypeLevel_43 "均衡等级";
CM_ SG_ 2417487467 S2P_Bal_SystemStatus_43 "均衡条件判断";
CM_ SG_ 2417487467 S2P_Bal_Strategy_43 "均衡策略";
CM_ SG_ 2417487467 S2P_Bal_ForceBalMode_43 "强制均衡模式";
CM_ SG_ 2417487467 S2P_Bal_CellTempFault_43 "温度单点无效";
CM_ SG_ 2417487467 S2P_Bal_CellVoltFail_43 "电芯电压采样失效";
CM_ SG_ 2417487467 S2P_Bal_CloseBalInstruct_43 "其他模块关闭均衡指令";
CM_ SG_ 2417487467 S2P_Bal_CCanTimeOut_43 "CCAN通讯超时故障";
CM_ SG_ 2417487467 S2P_Bal_CellOffLine_43 "预留";
CM_ SG_ 2417487467 S2P_Bal_BalanceCircuitFault_43 "均衡回路故障";
CM_ SG_ 2417487467 S2P_Bal_CSCSourceVoltFault_43 "CSC供电电压超限";
CM_ SG_ 2417487467 S2P_Bal_CellVoltOverFault_43 "预留";
CM_ SG_ 2417487467 S2P_Bal_CellVoltLowFault_43 "预留";
CM_ SG_ 2417487467 S2P_Bal_CSCPCBTempFault_43 "预留";
CM_ SG_ 2417487467 S2P_Bal_CSCSourceCurrLowFault_43 "CSC供电电流过低，禁止放电均衡";
CM_ SG_ 2417487467 S2P_Bal_CSCSourceCurrOvrFault_43 "CSC供电电流过高，禁止充电均衡";
CM_ SG_ 2417487468 S2P_Bal_CSCNum_44 "CSC号";
CM_ SG_ 2417487468 S2P_Bal_CellNum_44 "CELL号";
CM_ SG_ 2417487468 S2P_Bal_Type_44 "均衡类型";
CM_ SG_ 2417487468 S2P_Bal_TimeRemain_44 "均衡剩余时间";
CM_ SG_ 2417487468 S2P_Bal_DeltaVolt_44 "均衡电芯压差";
CM_ SG_ 2417487468 S2P_Bal_CSCPowerCurr_44 "CSC电源电流";
CM_ SG_ 2417487468 S2P_Bal_TypeLevel_44 "均衡等级";
CM_ SG_ 2417487468 S2P_Bal_SystemStatus_44 "均衡条件判断";
CM_ SG_ 2417487468 S2P_Bal_Strategy_44 "均衡策略";
CM_ SG_ 2417487468 S2P_Bal_ForceBalMode_44 "强制均衡模式";
CM_ SG_ 2417487468 S2P_Bal_CellTempFault_44 "温度单点无效";
CM_ SG_ 2417487468 S2P_Bal_CellVoltFail_44 "电芯电压采样失效";
CM_ SG_ 2417487468 S2P_Bal_CloseBalInstruct_44 "其他模块关闭均衡指令";
CM_ SG_ 2417487468 S2P_Bal_CCanTimeOut_44 "CCAN通讯超时故障";
CM_ SG_ 2417487468 S2P_Bal_CellOffLine_44 "预留";
CM_ SG_ 2417487468 S2P_Bal_BalanceCircuitFault_44 "均衡回路故障";
CM_ SG_ 2417487468 S2P_Bal_CSCSourceVoltFault_44 "CSC供电电压超限";
CM_ SG_ 2417487468 S2P_Bal_CellVoltOverFault_44 "预留";
CM_ SG_ 2417487468 S2P_Bal_CellVoltLowFault_44 "预留";
CM_ SG_ 2417487468 S2P_Bal_CSCPCBTempFault_44 "预留";
CM_ SG_ 2417487468 S2P_Bal_CSCSourceCurrLowFault_44 "CSC供电电流过低，禁止放电均衡";
CM_ SG_ 2417487468 S2P_Bal_CSCSourceCurrOvrFault_44 "CSC供电电流过高，禁止充电均衡";
CM_ SG_ 2417487469 S2P_Bal_CSCNum_45 "CSC号";
CM_ SG_ 2417487469 S2P_Bal_CellNum_45 "CELL号";
CM_ SG_ 2417487469 S2P_Bal_Type_45 "均衡类型";
CM_ SG_ 2417487469 S2P_Bal_TimeRemain_45 "均衡剩余时间";
CM_ SG_ 2417487469 S2P_Bal_DeltaVolt_45 "均衡电芯压差";
CM_ SG_ 2417487469 S2P_Bal_CSCPowerCurr_45 "CSC电源电流";
CM_ SG_ 2417487469 S2P_Bal_TypeLevel_45 "均衡等级";
CM_ SG_ 2417487469 S2P_Bal_SystemStatus_45 "均衡条件判断";
CM_ SG_ 2417487469 S2P_Bal_Strategy_45 "均衡策略";
CM_ SG_ 2417487469 S2P_Bal_ForceBalMode_45 "强制均衡模式";
CM_ SG_ 2417487469 S2P_Bal_CellTempFault_45 "温度单点无效";
CM_ SG_ 2417487469 S2P_Bal_CellVoltFail_45 "电芯电压采样失效";
CM_ SG_ 2417487469 S2P_Bal_CloseBalInstruct_45 "其他模块关闭均衡指令";
CM_ SG_ 2417487469 S2P_Bal_CCanTimeOut_45 "CCAN通讯超时故障";
CM_ SG_ 2417487469 S2P_Bal_CellOffLine_45 "预留";
CM_ SG_ 2417487469 S2P_Bal_BalanceCircuitFault_45 "均衡回路故障";
CM_ SG_ 2417487469 S2P_Bal_CSCSourceVoltFault_45 "CSC供电电压超限";
CM_ SG_ 2417487469 S2P_Bal_CellVoltOverFault_45 "预留";
CM_ SG_ 2417487469 S2P_Bal_CellVoltLowFault_45 "预留";
CM_ SG_ 2417487469 S2P_Bal_CSCPCBTempFault_45 "预留";
CM_ SG_ 2417487469 S2P_Bal_CSCSourceCurrLowFault_45 "CSC供电电流过低，禁止放电均衡";
CM_ SG_ 2417487469 S2P_Bal_CSCSourceCurrOvrFault_45 "CSC供电电流过高，禁止充电均衡";
CM_ SG_ 2417487470 S2P_Bal_CSCNum_46 "CSC号";
CM_ SG_ 2417487470 S2P_Bal_CellNum_46 "CELL号";
CM_ SG_ 2417487470 S2P_Bal_Type_46 "均衡类型";
CM_ SG_ 2417487470 S2P_Bal_TimeRemain_46 "均衡剩余时间";
CM_ SG_ 2417487470 S2P_Bal_DeltaVolt_46 "均衡电芯压差";
CM_ SG_ 2417487470 S2P_Bal_CSCPowerCurr_46 "CSC电源电流";
CM_ SG_ 2417487470 S2P_Bal_TypeLevel_46 "均衡等级";
CM_ SG_ 2417487470 S2P_Bal_SystemStatus_46 "均衡条件判断";
CM_ SG_ 2417487470 S2P_Bal_Strategy_46 "均衡策略";
CM_ SG_ 2417487470 S2P_Bal_ForceBalMode_46 "强制均衡模式";
CM_ SG_ 2417487470 S2P_Bal_CellTempFault_46 "温度单点无效";
CM_ SG_ 2417487470 S2P_Bal_CellVoltFail_46 "电芯电压采样失效";
CM_ SG_ 2417487470 S2P_Bal_CloseBalInstruct_46 "其他模块关闭均衡指令";
CM_ SG_ 2417487470 S2P_Bal_CCanTimeOut_46 "CCAN通讯超时故障";
CM_ SG_ 2417487470 S2P_Bal_CellOffLine_46 "预留";
CM_ SG_ 2417487470 S2P_Bal_BalanceCircuitFault_46 "均衡回路故障";
CM_ SG_ 2417487470 S2P_Bal_CSCSourceVoltFault_46 "CSC供电电压超限";
CM_ SG_ 2417487470 S2P_Bal_CellVoltOverFault_46 "预留";
CM_ SG_ 2417487470 S2P_Bal_CellVoltLowFault_46 "预留";
CM_ SG_ 2417487470 S2P_Bal_CSCPCBTempFault_46 "预留";
CM_ SG_ 2417487470 S2P_Bal_CSCSourceCurrLowFault_46 "CSC供电电流过低，禁止放电均衡";
CM_ SG_ 2417487470 S2P_Bal_CSCSourceCurrOvrFault_46 "CSC供电电流过高，禁止充电均衡";
CM_ SG_ 2417487471 S2P_Bal_CSCNum_47 "CSC号";
CM_ SG_ 2417487471 S2P_Bal_CellNum_47 "CELL号";
CM_ SG_ 2417487471 S2P_Bal_Type_47 "均衡类型";
CM_ SG_ 2417487471 S2P_Bal_TimeRemain_47 "均衡剩余时间";
CM_ SG_ 2417487471 S2P_Bal_DeltaVolt_47 "均衡电芯压差";
CM_ SG_ 2417487471 S2P_Bal_CSCPowerCurr_47 "CSC电源电流";
CM_ SG_ 2417487471 S2P_Bal_TypeLevel_47 "均衡等级";
CM_ SG_ 2417487471 S2P_Bal_SystemStatus_47 "均衡条件判断";
CM_ SG_ 2417487471 S2P_Bal_Strategy_47 "均衡策略";
CM_ SG_ 2417487471 S2P_Bal_ForceBalMode_47 "强制均衡模式";
CM_ SG_ 2417487471 S2P_Bal_CellTempFault_47 "温度单点无效";
CM_ SG_ 2417487471 S2P_Bal_CellVoltFail_47 "电芯电压采样失效";
CM_ SG_ 2417487471 S2P_Bal_CloseBalInstruct_47 "其他模块关闭均衡指令";
CM_ SG_ 2417487471 S2P_Bal_CCanTimeOut_47 "CCAN通讯超时故障";
CM_ SG_ 2417487471 S2P_Bal_CellOffLine_47 "预留";
CM_ SG_ 2417487471 S2P_Bal_BalanceCircuitFault_47 "均衡回路故障";
CM_ SG_ 2417487471 S2P_Bal_CSCSourceVoltFault_47 "CSC供电电压超限";
CM_ SG_ 2417487471 S2P_Bal_CellVoltOverFault_47 "预留";
CM_ SG_ 2417487471 S2P_Bal_CellVoltLowFault_47 "预留";
CM_ SG_ 2417487471 S2P_Bal_CSCPCBTempFault_47 "预留";
CM_ SG_ 2417487471 S2P_Bal_CSCSourceCurrLowFault_47 "CSC供电电流过低，禁止放电均衡";
CM_ SG_ 2417487471 S2P_Bal_CSCSourceCurrOvrFault_47 "CSC供电电流过高，禁止充电均衡";
CM_ SG_ 2417487472 S2P_Bal_CSCNum_48 "CSC号";
CM_ SG_ 2417487472 S2P_Bal_CellNum_48 "CELL号";
CM_ SG_ 2417487472 S2P_Bal_Type_48 "均衡类型";
CM_ SG_ 2417487472 S2P_Bal_TimeRemain_48 "均衡剩余时间";
CM_ SG_ 2417487472 S2P_Bal_DeltaVolt_48 "均衡电芯压差";
CM_ SG_ 2417487472 S2P_Bal_CSCPowerCurr_48 "CSC电源电流";
CM_ SG_ 2417487472 S2P_Bal_TypeLevel_48 "均衡等级";
CM_ SG_ 2417487472 S2P_Bal_SystemStatus_48 "均衡条件判断";
CM_ SG_ 2417487472 S2P_Bal_Strategy_48 "均衡策略";
CM_ SG_ 2417487472 S2P_Bal_ForceBalMode_48 "强制均衡模式";
CM_ SG_ 2417487472 S2P_Bal_CellTempFault_48 "温度单点无效";
CM_ SG_ 2417487472 S2P_Bal_CellVoltFail_48 "电芯电压采样失效";
CM_ SG_ 2417487472 S2P_Bal_CloseBalInstruct_48 "其他模块关闭均衡指令";
CM_ SG_ 2417487472 S2P_Bal_CCanTimeOut_48 "CCAN通讯超时故障";
CM_ SG_ 2417487472 S2P_Bal_CellOffLine_48 "预留";
CM_ SG_ 2417487472 S2P_Bal_BalanceCircuitFault_48 "均衡回路故障";
CM_ SG_ 2417487472 S2P_Bal_CSCSourceVoltFault_48 "CSC供电电压超限";
CM_ SG_ 2417487472 S2P_Bal_CellVoltOverFault_48 "预留";
CM_ SG_ 2417487472 S2P_Bal_CellVoltLowFault_48 "预留";
CM_ SG_ 2417487472 S2P_Bal_CSCPCBTempFault_48 "预留";
CM_ SG_ 2417487472 S2P_Bal_CSCSourceCurrLowFault_48 "CSC供电电流过低，禁止放电均衡";
CM_ SG_ 2417487472 S2P_Bal_CSCSourceCurrOvrFault_48 "CSC供电电流过高，禁止充电均衡";
CM_ SG_ 2417487473 S2P_Bal_CSCNum_49 "CSC号";
CM_ SG_ 2417487473 S2P_Bal_CellNum_49 "CELL号";
CM_ SG_ 2417487473 S2P_Bal_Type_49 "均衡类型";
CM_ SG_ 2417487473 S2P_Bal_TimeRemain_49 "均衡剩余时间";
CM_ SG_ 2417487473 S2P_Bal_DeltaVolt_49 "均衡电芯压差";
CM_ SG_ 2417487473 S2P_Bal_CSCPowerCurr_49 "CSC电源电流";
CM_ SG_ 2417487473 S2P_Bal_TypeLevel_49 "均衡等级";
CM_ SG_ 2417487473 S2P_Bal_SystemStatus_49 "均衡条件判断";
CM_ SG_ 2417487473 S2P_Bal_Strategy_49 "均衡策略";
CM_ SG_ 2417487473 S2P_Bal_ForceBalMode_49 "强制均衡模式";
CM_ SG_ 2417487473 S2P_Bal_CellTempFault_49 "温度单点无效";
CM_ SG_ 2417487473 S2P_Bal_CellVoltFail_49 "电芯电压采样失效";
CM_ SG_ 2417487473 S2P_Bal_CloseBalInstruct_49 "其他模块关闭均衡指令";
CM_ SG_ 2417487473 S2P_Bal_CCanTimeOut_49 "CCAN通讯超时故障";
CM_ SG_ 2417487473 S2P_Bal_CellOffLine_49 "预留";
CM_ SG_ 2417487473 S2P_Bal_BalanceCircuitFault_49 "均衡回路故障";
CM_ SG_ 2417487473 S2P_Bal_CSCSourceVoltFault_49 "CSC供电电压超限";
CM_ SG_ 2417487473 S2P_Bal_CellVoltOverFault_49 "预留";
CM_ SG_ 2417487473 S2P_Bal_CellVoltLowFault_49 "预留";
CM_ SG_ 2417487473 S2P_Bal_CSCPCBTempFault_49 "预留";
CM_ SG_ 2417487473 S2P_Bal_CSCSourceCurrLowFault_49 "CSC供电电流过低，禁止放电均衡";
CM_ SG_ 2417487473 S2P_Bal_CSCSourceCurrOvrFault_49 "CSC供电电流过高，禁止充电均衡";
CM_ SG_ 2417487474 S2P_Bal_CSCNum_50 "CSC号";
CM_ SG_ 2417487474 S2P_Bal_CellNum_50 "CELL号";
CM_ SG_ 2417487474 S2P_Bal_Type_50 "均衡类型";
CM_ SG_ 2417487474 S2P_Bal_TimeRemain_50 "均衡剩余时间";
CM_ SG_ 2417487474 S2P_Bal_DeltaVolt_50 "均衡电芯压差";
CM_ SG_ 2417487474 S2P_Bal_CSCPowerCurr_50 "CSC电源电流";
CM_ SG_ 2417487474 S2P_Bal_TypeLevel_50 "均衡等级";
CM_ SG_ 2417487474 S2P_Bal_SystemStatus_50 "均衡条件判断";
CM_ SG_ 2417487474 S2P_Bal_Strategy_50 "均衡策略";
CM_ SG_ 2417487474 S2P_Bal_ForceBalMode_50 "强制均衡模式";
CM_ SG_ 2417487474 S2P_Bal_CellTempFault_50 "温度单点无效";
CM_ SG_ 2417487474 S2P_Bal_CellVoltFail_50 "电芯电压采样失效";
CM_ SG_ 2417487474 S2P_Bal_CloseBalInstruct_50 "其他模块关闭均衡指令";
CM_ SG_ 2417487474 S2P_Bal_CCanTimeOut_50 "CCAN通讯超时故障";
CM_ SG_ 2417487474 S2P_Bal_CellOffLine_50 "预留";
CM_ SG_ 2417487474 S2P_Bal_BalanceCircuitFault_50 "均衡回路故障";
CM_ SG_ 2417487474 S2P_Bal_CSCSourceVoltFault_50 "CSC供电电压超限";
CM_ SG_ 2417487474 S2P_Bal_CellVoltOverFault_50 "预留";
CM_ SG_ 2417487474 S2P_Bal_CellVoltLowFault_50 "预留";
CM_ SG_ 2417487474 S2P_Bal_CSCPCBTempFault_50 "预留";
CM_ SG_ 2417487474 S2P_Bal_CSCSourceCurrLowFault_50 "CSC供电电流过低，禁止放电均衡";
CM_ SG_ 2417487474 S2P_Bal_CSCSourceCurrOvrFault_50 "CSC供电电流过高，禁止充电均衡";
CM_ SG_ 2417487475 S2P_Bal_CSCNum_51 "CSC号";
CM_ SG_ 2417487475 S2P_Bal_CellNum_51 "CELL号";
CM_ SG_ 2417487475 S2P_Bal_Type_51 "均衡类型";
CM_ SG_ 2417487475 S2P_Bal_TimeRemain_51 "均衡剩余时间";
CM_ SG_ 2417487475 S2P_Bal_DeltaVolt_51 "均衡电芯压差";
CM_ SG_ 2417487475 S2P_Bal_CSCPowerCurr_51 "CSC电源电流";
CM_ SG_ 2417487475 S2P_Bal_TypeLevel_51 "均衡等级";
CM_ SG_ 2417487475 S2P_Bal_SystemStatus_51 "均衡条件判断";
CM_ SG_ 2417487475 S2P_Bal_Strategy_51 "均衡策略";
CM_ SG_ 2417487475 S2P_Bal_ForceBalMode_51 "强制均衡模式";
CM_ SG_ 2417487475 S2P_Bal_CellTempFault_51 "温度单点无效";
CM_ SG_ 2417487475 S2P_Bal_CellVoltFail_51 "电芯电压采样失效";
CM_ SG_ 2417487475 S2P_Bal_CloseBalInstruct_51 "其他模块关闭均衡指令";
CM_ SG_ 2417487475 S2P_Bal_CCanTimeOut_51 "CCAN通讯超时故障";
CM_ SG_ 2417487475 S2P_Bal_CellOffLine_51 "预留";
CM_ SG_ 2417487475 S2P_Bal_BalanceCircuitFault_51 "均衡回路故障";
CM_ SG_ 2417487475 S2P_Bal_CSCSourceVoltFault_51 "CSC供电电压超限";
CM_ SG_ 2417487475 S2P_Bal_CellVoltOverFault_51 "预留";
CM_ SG_ 2417487475 S2P_Bal_CellVoltLowFault_51 "预留";
CM_ SG_ 2417487475 S2P_Bal_CSCPCBTempFault_51 "预留";
CM_ SG_ 2417487475 S2P_Bal_CSCSourceCurrLowFault_51 "CSC供电电流过低，禁止放电均衡";
CM_ SG_ 2417487475 S2P_Bal_CSCSourceCurrOvrFault_51 "CSC供电电流过高，禁止充电均衡";
CM_ SG_ 2417487476 S2P_Bal_CSCNum_52 "CSC号";
CM_ SG_ 2417487476 S2P_Bal_CellNum_52 "CELL号";
CM_ SG_ 2417487476 S2P_Bal_Type_52 "均衡类型";
CM_ SG_ 2417487476 S2P_Bal_TimeRemain_52 "均衡剩余时间";
CM_ SG_ 2417487476 S2P_Bal_DeltaVolt_52 "均衡电芯压差";
CM_ SG_ 2417487476 S2P_Bal_CSCPowerCurr_52 "CSC电源电流";
CM_ SG_ 2417487476 S2P_Bal_TypeLevel_52 "均衡等级";
CM_ SG_ 2417487476 S2P_Bal_SystemStatus_52 "均衡条件判断";
CM_ SG_ 2417487476 S2P_Bal_Strategy_52 "均衡策略";
CM_ SG_ 2417487476 S2P_Bal_ForceBalMode_52 "强制均衡模式";
CM_ SG_ 2417487476 S2P_Bal_CellTempFault_52 "温度单点无效";
CM_ SG_ 2417487476 S2P_Bal_CellVoltFail_52 "电芯电压采样失效";
CM_ SG_ 2417487476 S2P_Bal_CloseBalInstruct_52 "其他模块关闭均衡指令";
CM_ SG_ 2417487476 S2P_Bal_CCanTimeOut_52 "CCAN通讯超时故障";
CM_ SG_ 2417487476 S2P_Bal_CellOffLine_52 "预留";
CM_ SG_ 2417487476 S2P_Bal_BalanceCircuitFault_52 "均衡回路故障";
CM_ SG_ 2417487476 S2P_Bal_CSCSourceVoltFault_52 "CSC供电电压超限";
CM_ SG_ 2417487476 S2P_Bal_CellVoltOverFault_52 "预留";
CM_ SG_ 2417487476 S2P_Bal_CellVoltLowFault_52 "预留";
CM_ SG_ 2417487476 S2P_Bal_CSCPCBTempFault_52 "预留";
CM_ SG_ 2417487476 S2P_Bal_CSCSourceCurrLowFault_52 "CSC供电电流过低，禁止放电均衡";
CM_ SG_ 2417487476 S2P_Bal_CSCSourceCurrOvrFault_52 "CSC供电电流过高，禁止充电均衡";
CM_ SG_ 2417487477 S2P_Bal_CSCNum_53 "CSC号";
CM_ SG_ 2417487477 S2P_Bal_CellNum_53 "CELL号";
CM_ SG_ 2417487477 S2P_Bal_Type_53 "均衡类型";
CM_ SG_ 2417487477 S2P_Bal_TimeRemain_53 "均衡剩余时间";
CM_ SG_ 2417487477 S2P_Bal_DeltaVolt_53 "均衡电芯压差";
CM_ SG_ 2417487477 S2P_Bal_CSCPowerCurr_53 "CSC电源电流";
CM_ SG_ 2417487477 S2P_Bal_TypeLevel_53 "均衡等级";
CM_ SG_ 2417487477 S2P_Bal_SystemStatus_53 "均衡条件判断";
CM_ SG_ 2417487477 S2P_Bal_Strategy_53 "均衡策略";
CM_ SG_ 2417487477 S2P_Bal_ForceBalMode_53 "强制均衡模式";
CM_ SG_ 2417487477 S2P_Bal_CellTempFault_53 "温度单点无效";
CM_ SG_ 2417487477 S2P_Bal_CellVoltFail_53 "电芯电压采样失效";
CM_ SG_ 2417487477 S2P_Bal_CloseBalInstruct_53 "其他模块关闭均衡指令";
CM_ SG_ 2417487477 S2P_Bal_CCanTimeOut_53 "CCAN通讯超时故障";
CM_ SG_ 2417487477 S2P_Bal_CellOffLine_53 "预留";
CM_ SG_ 2417487477 S2P_Bal_BalanceCircuitFault_53 "均衡回路故障";
CM_ SG_ 2417487477 S2P_Bal_CSCSourceVoltFault_53 "CSC供电电压超限";
CM_ SG_ 2417487477 S2P_Bal_CellVoltOverFault_53 "预留";
CM_ SG_ 2417487477 S2P_Bal_CellVoltLowFault_53 "预留";
CM_ SG_ 2417487477 S2P_Bal_CSCPCBTempFault_53 "预留";
CM_ SG_ 2417487477 S2P_Bal_CSCSourceCurrLowFault_53 "CSC供电电流过低，禁止放电均衡";
CM_ SG_ 2417487477 S2P_Bal_CSCSourceCurrOvrFault_53 "CSC供电电流过高，禁止充电均衡";
CM_ SG_ 2417487478 S2P_Bal_CSCNum_54 "CSC号";
CM_ SG_ 2417487478 S2P_Bal_CellNum_54 "CELL号";
CM_ SG_ 2417487478 S2P_Bal_Type_54 "均衡类型";
CM_ SG_ 2417487478 S2P_Bal_TimeRemain_54 "均衡剩余时间";
CM_ SG_ 2417487478 S2P_Bal_DeltaVolt_54 "均衡电芯压差";
CM_ SG_ 2417487478 S2P_Bal_CSCPowerCurr_54 "CSC电源电流";
CM_ SG_ 2417487478 S2P_Bal_TypeLevel_54 "均衡等级";
CM_ SG_ 2417487478 S2P_Bal_SystemStatus_54 "均衡条件判断";
CM_ SG_ 2417487478 S2P_Bal_Strategy_54 "均衡策略";
CM_ SG_ 2417487478 S2P_Bal_ForceBalMode_54 "强制均衡模式";
CM_ SG_ 2417487478 S2P_Bal_CellTempFault_54 "温度单点无效";
CM_ SG_ 2417487478 S2P_Bal_CellVoltFail_54 "电芯电压采样失效";
CM_ SG_ 2417487478 S2P_Bal_CloseBalInstruct_54 "其他模块关闭均衡指令";
CM_ SG_ 2417487478 S2P_Bal_CCanTimeOut_54 "CCAN通讯超时故障";
CM_ SG_ 2417487478 S2P_Bal_CellOffLine_54 "预留";
CM_ SG_ 2417487478 S2P_Bal_BalanceCircuitFault_54 "均衡回路故障";
CM_ SG_ 2417487478 S2P_Bal_CSCSourceVoltFault_54 "CSC供电电压超限";
CM_ SG_ 2417487478 S2P_Bal_CellVoltOverFault_54 "预留";
CM_ SG_ 2417487478 S2P_Bal_CellVoltLowFault_54 "预留";
CM_ SG_ 2417487478 S2P_Bal_CSCPCBTempFault_54 "预留";
CM_ SG_ 2417487478 S2P_Bal_CSCSourceCurrLowFault_54 "CSC供电电流过低，禁止放电均衡";
CM_ SG_ 2417487478 S2P_Bal_CSCSourceCurrOvrFault_54 "CSC供电电流过高，禁止充电均衡";
CM_ SG_ 2417487479 S2P_Bal_CSCNum_55 "CSC号";
CM_ SG_ 2417487479 S2P_Bal_CellNum_55 "CELL号";
CM_ SG_ 2417487479 S2P_Bal_Type_55 "均衡类型";
CM_ SG_ 2417487479 S2P_Bal_TimeRemain_55 "均衡剩余时间";
CM_ SG_ 2417487479 S2P_Bal_DeltaVolt_55 "均衡电芯压差";
CM_ SG_ 2417487479 S2P_Bal_CSCPowerCurr_55 "CSC电源电流";
CM_ SG_ 2417487479 S2P_Bal_TypeLevel_55 "均衡等级";
CM_ SG_ 2417487479 S2P_Bal_SystemStatus_55 "均衡条件判断";
CM_ SG_ 2417487479 S2P_Bal_Strategy_55 "均衡策略";
CM_ SG_ 2417487479 S2P_Bal_ForceBalMode_55 "强制均衡模式";
CM_ SG_ 2417487479 S2P_Bal_CellTempFault_55 "温度单点无效";
CM_ SG_ 2417487479 S2P_Bal_CellVoltFail_55 "电芯电压采样失效";
CM_ SG_ 2417487479 S2P_Bal_CloseBalInstruct_55 "其他模块关闭均衡指令";
CM_ SG_ 2417487479 S2P_Bal_CCanTimeOut_55 "CCAN通讯超时故障";
CM_ SG_ 2417487479 S2P_Bal_CellOffLine_55 "预留";
CM_ SG_ 2417487479 S2P_Bal_BalanceCircuitFault_55 "均衡回路故障";
CM_ SG_ 2417487479 S2P_Bal_CSCSourceVoltFault_55 "CSC供电电压超限";
CM_ SG_ 2417487479 S2P_Bal_CellVoltOverFault_55 "预留";
CM_ SG_ 2417487479 S2P_Bal_CellVoltLowFault_55 "预留";
CM_ SG_ 2417487479 S2P_Bal_CSCPCBTempFault_55 "预留";
CM_ SG_ 2417487479 S2P_Bal_CSCSourceCurrLowFault_55 "CSC供电电流过低，禁止放电均衡";
CM_ SG_ 2417487479 S2P_Bal_CSCSourceCurrOvrFault_55 "CSC供电电流过高，禁止充电均衡";
CM_ SG_ 2417487480 S2P_Bal_CSCNum_56 "CSC号";
CM_ SG_ 2417487480 S2P_Bal_CellNum_56 "CELL号";
CM_ SG_ 2417487480 S2P_Bal_Type_56 "均衡类型";
CM_ SG_ 2417487480 S2P_Bal_TimeRemain_56 "均衡剩余时间";
CM_ SG_ 2417487480 S2P_Bal_DeltaVolt_56 "均衡电芯压差";
CM_ SG_ 2417487480 S2P_Bal_CSCPowerCurr_56 "CSC电源电流";
CM_ SG_ 2417487480 S2P_Bal_TypeLevel_56 "均衡等级";
CM_ SG_ 2417487480 S2P_Bal_SystemStatus_56 "均衡条件判断";
CM_ SG_ 2417487480 S2P_Bal_Strategy_56 "均衡策略";
CM_ SG_ 2417487480 S2P_Bal_ForceBalMode_56 "强制均衡模式";
CM_ SG_ 2417487480 S2P_Bal_CellTempFault_56 "温度单点无效";
CM_ SG_ 2417487480 S2P_Bal_CellVoltFail_56 "电芯电压采样失效";
CM_ SG_ 2417487480 S2P_Bal_CloseBalInstruct_56 "其他模块关闭均衡指令";
CM_ SG_ 2417487480 S2P_Bal_CCanTimeOut_56 "CCAN通讯超时故障";
CM_ SG_ 2417487480 S2P_Bal_CellOffLine_56 "预留";
CM_ SG_ 2417487480 S2P_Bal_BalanceCircuitFault_56 "均衡回路故障";
CM_ SG_ 2417487480 S2P_Bal_CSCSourceVoltFault_56 "CSC供电电压超限";
CM_ SG_ 2417487480 S2P_Bal_CellVoltOverFault_56 "预留";
CM_ SG_ 2417487480 S2P_Bal_CellVoltLowFault_56 "预留";
CM_ SG_ 2417487480 S2P_Bal_CSCPCBTempFault_56 "预留";
CM_ SG_ 2417487480 S2P_Bal_CSCSourceCurrLowFault_56 "CSC供电电流过低，禁止放电均衡";
CM_ SG_ 2417487480 S2P_Bal_CSCSourceCurrOvrFault_56 "CSC供电电流过高，禁止充电均衡";
CM_ SG_ 2417487481 S2P_Bal_CSCNum_57 "CSC号";
CM_ SG_ 2417487481 S2P_Bal_CellNum_57 "CELL号";
CM_ SG_ 2417487481 S2P_Bal_Type_57 "均衡类型";
CM_ SG_ 2417487481 S2P_Bal_TimeRemain_57 "均衡剩余时间";
CM_ SG_ 2417487481 S2P_Bal_DeltaVolt_57 "均衡电芯压差";
CM_ SG_ 2417487481 S2P_Bal_CSCPowerCurr_57 "CSC电源电流";
CM_ SG_ 2417487481 S2P_Bal_TypeLevel_57 "均衡等级";
CM_ SG_ 2417487481 S2P_Bal_SystemStatus_57 "均衡条件判断";
CM_ SG_ 2417487481 S2P_Bal_Strategy_57 "均衡策略";
CM_ SG_ 2417487481 S2P_Bal_ForceBalMode_57 "强制均衡模式";
CM_ SG_ 2417487481 S2P_Bal_CellTempFault_57 "温度单点无效";
CM_ SG_ 2417487481 S2P_Bal_CellVoltFail_57 "电芯电压采样失效";
CM_ SG_ 2417487481 S2P_Bal_CloseBalInstruct_57 "其他模块关闭均衡指令";
CM_ SG_ 2417487481 S2P_Bal_CCanTimeOut_57 "CCAN通讯超时故障";
CM_ SG_ 2417487481 S2P_Bal_CellOffLine_57 "预留";
CM_ SG_ 2417487481 S2P_Bal_BalanceCircuitFault_57 "均衡回路故障";
CM_ SG_ 2417487481 S2P_Bal_CSCSourceVoltFault_57 "CSC供电电压超限";
CM_ SG_ 2417487481 S2P_Bal_CellVoltOverFault_57 "预留";
CM_ SG_ 2417487481 S2P_Bal_CellVoltLowFault_57 "预留";
CM_ SG_ 2417487481 S2P_Bal_CSCPCBTempFault_57 "预留";
CM_ SG_ 2417487481 S2P_Bal_CSCSourceCurrLowFault_57 "CSC供电电流过低，禁止放电均衡";
CM_ SG_ 2417487481 S2P_Bal_CSCSourceCurrOvrFault_57 "CSC供电电流过高，禁止充电均衡";
CM_ SG_ 2417487482 S2P_Bal_CSCNum_58 "CSC号";
CM_ SG_ 2417487482 S2P_Bal_CellNum_58 "CELL号";
CM_ SG_ 2417487482 S2P_Bal_Type_58 "均衡类型";
CM_ SG_ 2417487482 S2P_Bal_TimeRemain_58 "均衡剩余时间";
CM_ SG_ 2417487482 S2P_Bal_DeltaVolt_58 "均衡电芯压差";
CM_ SG_ 2417487482 S2P_Bal_CSCPowerCurr_58 "CSC电源电流";
CM_ SG_ 2417487482 S2P_Bal_TypeLevel_58 "均衡等级";
CM_ SG_ 2417487482 S2P_Bal_SystemStatus_58 "均衡条件判断";
CM_ SG_ 2417487482 S2P_Bal_Strategy_58 "均衡策略";
CM_ SG_ 2417487482 S2P_Bal_ForceBalMode_58 "强制均衡模式";
CM_ SG_ 2417487482 S2P_Bal_CellTempFault_58 "温度单点无效";
CM_ SG_ 2417487482 S2P_Bal_CellVoltFail_58 "电芯电压采样失效";
CM_ SG_ 2417487482 S2P_Bal_CloseBalInstruct_58 "其他模块关闭均衡指令";
CM_ SG_ 2417487482 S2P_Bal_CCanTimeOut_58 "CCAN通讯超时故障";
CM_ SG_ 2417487482 S2P_Bal_CellOffLine_58 "预留";
CM_ SG_ 2417487482 S2P_Bal_BalanceCircuitFault_58 "均衡回路故障";
CM_ SG_ 2417487482 S2P_Bal_CSCSourceVoltFault_58 "CSC供电电压超限";
CM_ SG_ 2417487482 S2P_Bal_CellVoltOverFault_58 "预留";
CM_ SG_ 2417487482 S2P_Bal_CellVoltLowFault_58 "预留";
CM_ SG_ 2417487482 S2P_Bal_CSCPCBTempFault_58 "预留";
CM_ SG_ 2417487482 S2P_Bal_CSCSourceCurrLowFault_58 "CSC供电电流过低，禁止放电均衡";
CM_ SG_ 2417487482 S2P_Bal_CSCSourceCurrOvrFault_58 "CSC供电电流过高，禁止充电均衡";
CM_ SG_ 2417487483 S2P_Bal_CSCNum_59 "CSC号";
CM_ SG_ 2417487483 S2P_Bal_CellNum_59 "CELL号";
CM_ SG_ 2417487483 S2P_Bal_Type_59 "均衡类型";
CM_ SG_ 2417487483 S2P_Bal_TimeRemain_59 "均衡剩余时间";
CM_ SG_ 2417487483 S2P_Bal_DeltaVolt_59 "均衡电芯压差";
CM_ SG_ 2417487483 S2P_Bal_CSCPowerCurr_59 "CSC电源电流";
CM_ SG_ 2417487483 S2P_Bal_TypeLevel_59 "均衡等级";
CM_ SG_ 2417487483 S2P_Bal_SystemStatus_59 "均衡条件判断";
CM_ SG_ 2417487483 S2P_Bal_Strategy_59 "均衡策略";
CM_ SG_ 2417487483 S2P_Bal_ForceBalMode_59 "强制均衡模式";
CM_ SG_ 2417487483 S2P_Bal_CellTempFault_59 "温度单点无效";
CM_ SG_ 2417487483 S2P_Bal_CellVoltFail_59 "电芯电压采样失效";
CM_ SG_ 2417487483 S2P_Bal_CloseBalInstruct_59 "其他模块关闭均衡指令";
CM_ SG_ 2417487483 S2P_Bal_CCanTimeOut_59 "CCAN通讯超时故障";
CM_ SG_ 2417487483 S2P_Bal_CellOffLine_59 "预留";
CM_ SG_ 2417487483 S2P_Bal_BalanceCircuitFault_59 "均衡回路故障";
CM_ SG_ 2417487483 S2P_Bal_CSCSourceVoltFault_59 "CSC供电电压超限";
CM_ SG_ 2417487483 S2P_Bal_CellVoltOverFault_59 "预留";
CM_ SG_ 2417487483 S2P_Bal_CellVoltLowFault_59 "预留";
CM_ SG_ 2417487483 S2P_Bal_CSCPCBTempFault_59 "预留";
CM_ SG_ 2417487483 S2P_Bal_CSCSourceCurrLowFault_59 "CSC供电电流过低，禁止放电均衡";
CM_ SG_ 2417487483 S2P_Bal_CSCSourceCurrOvrFault_59 "CSC供电电流过高，禁止充电均衡";
CM_ SG_ 2417487484 S2P_Bal_CSCNum_60 "CSC号";
CM_ SG_ 2417487484 S2P_Bal_CellNum_60 "CELL号";
CM_ SG_ 2417487484 S2P_Bal_Type_60 "均衡类型";
CM_ SG_ 2417487484 S2P_Bal_TimeRemain_60 "均衡剩余时间";
CM_ SG_ 2417487484 S2P_Bal_DeltaVolt_60 "均衡电芯压差";
CM_ SG_ 2417487484 S2P_Bal_CSCPowerCurr_60 "CSC电源电流";
CM_ SG_ 2417487484 S2P_Bal_TypeLevel_60 "均衡等级";
CM_ SG_ 2417487484 S2P_Bal_SystemStatus_60 "均衡条件判断";
CM_ SG_ 2417487484 S2P_Bal_Strategy_60 "均衡策略";
CM_ SG_ 2417487484 S2P_Bal_ForceBalMode_60 "强制均衡模式";
CM_ SG_ 2417487484 S2P_Bal_CellTempFault_60 "温度单点无效";
CM_ SG_ 2417487484 S2P_Bal_CellVoltFail_60 "电芯电压采样失效";
CM_ SG_ 2417487484 S2P_Bal_CloseBalInstruct_60 "其他模块关闭均衡指令";
CM_ SG_ 2417487484 S2P_Bal_CCanTimeOut_60 "CCAN通讯超时故障";
CM_ SG_ 2417487484 S2P_Bal_CellOffLine_60 "预留";
CM_ SG_ 2417487484 S2P_Bal_BalanceCircuitFault_60 "均衡回路故障";
CM_ SG_ 2417487484 S2P_Bal_CSCSourceVoltFault_60 "CSC供电电压超限";
CM_ SG_ 2417487484 S2P_Bal_CellVoltOverFault_60 "预留";
CM_ SG_ 2417487484 S2P_Bal_CellVoltLowFault_60 "预留";
CM_ SG_ 2417487484 S2P_Bal_CSCPCBTempFault_60 "预留";
CM_ SG_ 2417487484 S2P_Bal_CSCSourceCurrLowFault_60 "CSC供电电流过低，禁止放电均衡";
CM_ SG_ 2417487484 S2P_Bal_CSCSourceCurrOvrFault_60 "CSC供电电流过高，禁止充电均衡";
CM_ SG_ 2417487485 S2P_Bal_CSCNum_61 "CSC号";
CM_ SG_ 2417487485 S2P_Bal_CellNum_61 "CELL号";
CM_ SG_ 2417487485 S2P_Bal_Type_61 "均衡类型";
CM_ SG_ 2417487485 S2P_Bal_TimeRemain_61 "均衡剩余时间";
CM_ SG_ 2417487485 S2P_Bal_DeltaVolt_61 "均衡电芯压差";
CM_ SG_ 2417487485 S2P_Bal_CSCPowerCurr_61 "CSC电源电流";
CM_ SG_ 2417487485 S2P_Bal_TypeLevel_61 "均衡等级";
CM_ SG_ 2417487485 S2P_Bal_SystemStatus_61 "均衡条件判断";
CM_ SG_ 2417487485 S2P_Bal_Strategy_61 "均衡策略";
CM_ SG_ 2417487485 S2P_Bal_ForceBalMode_61 "强制均衡模式";
CM_ SG_ 2417487485 S2P_Bal_CellTempFault_61 "温度单点无效";
CM_ SG_ 2417487485 S2P_Bal_CellVoltFail_61 "电芯电压采样失效";
CM_ SG_ 2417487485 S2P_Bal_CloseBalInstruct_61 "其他模块关闭均衡指令";
CM_ SG_ 2417487485 S2P_Bal_CCanTimeOut_61 "CCAN通讯超时故障";
CM_ SG_ 2417487485 S2P_Bal_CellOffLine_61 "预留";
CM_ SG_ 2417487485 S2P_Bal_BalanceCircuitFault_61 "均衡回路故障";
CM_ SG_ 2417487485 S2P_Bal_CSCSourceVoltFault_61 "CSC供电电压超限";
CM_ SG_ 2417487485 S2P_Bal_CellVoltOverFault_61 "预留";
CM_ SG_ 2417487485 S2P_Bal_CellVoltLowFault_61 "预留";
CM_ SG_ 2417487485 S2P_Bal_CSCPCBTempFault_61 "预留";
CM_ SG_ 2417487485 S2P_Bal_CSCSourceCurrLowFault_61 "CSC供电电流过低，禁止放电均衡";
CM_ SG_ 2417487485 S2P_Bal_CSCSourceCurrOvrFault_61 "CSC供电电流过高，禁止充电均衡";
CM_ SG_ 2417487486 S2P_Bal_CSCNum_62 "CSC号";
CM_ SG_ 2417487486 S2P_Bal_CellNum_62 "CELL号";
CM_ SG_ 2417487486 S2P_Bal_Type_62 "均衡类型";
CM_ SG_ 2417487486 S2P_Bal_TimeRemain_62 "均衡剩余时间";
CM_ SG_ 2417487486 S2P_Bal_DeltaVolt_62 "均衡电芯压差";
CM_ SG_ 2417487486 S2P_Bal_CSCPowerCurr_62 "CSC电源电流";
CM_ SG_ 2417487486 S2P_Bal_TypeLevel_62 "均衡等级";
CM_ SG_ 2417487486 S2P_Bal_SystemStatus_62 "均衡条件判断";
CM_ SG_ 2417487486 S2P_Bal_Strategy_62 "均衡策略";
CM_ SG_ 2417487486 S2P_Bal_ForceBalMode_62 "强制均衡模式";
CM_ SG_ 2417487486 S2P_Bal_CellTempFault_62 "温度单点无效";
CM_ SG_ 2417487486 S2P_Bal_CellVoltFail_62 "电芯电压采样失效";
CM_ SG_ 2417487486 S2P_Bal_CloseBalInstruct_62 "其他模块关闭均衡指令";
CM_ SG_ 2417487486 S2P_Bal_CCanTimeOut_62 "CCAN通讯超时故障";
CM_ SG_ 2417487486 S2P_Bal_CellOffLine_62 "预留";
CM_ SG_ 2417487486 S2P_Bal_BalanceCircuitFault_62 "均衡回路故障";
CM_ SG_ 2417487486 S2P_Bal_CSCSourceVoltFault_62 "CSC供电电压超限";
CM_ SG_ 2417487486 S2P_Bal_CellVoltOverFault_62 "预留";
CM_ SG_ 2417487486 S2P_Bal_CellVoltLowFault_62 "预留";
CM_ SG_ 2417487486 S2P_Bal_CSCPCBTempFault_62 "预留";
CM_ SG_ 2417487486 S2P_Bal_CSCSourceCurrLowFault_62 "CSC供电电流过低，禁止放电均衡";
CM_ SG_ 2417487486 S2P_Bal_CSCSourceCurrOvrFault_62 "CSC供电电流过高，禁止充电均衡";
CM_ SG_ 2417487487 S2P_Bal_CSCNum_63 "CSC号";
CM_ SG_ 2417487487 S2P_Bal_CellNum_63 "CELL号";
CM_ SG_ 2417487487 S2P_Bal_Type_63 "均衡类型";
CM_ SG_ 2417487487 S2P_Bal_TimeRemain_63 "均衡剩余时间";
CM_ SG_ 2417487487 S2P_Bal_DeltaVolt_63 "均衡电芯压差";
CM_ SG_ 2417487487 S2P_Bal_CSCPowerCurr_63 "CSC电源电流";
CM_ SG_ 2417487487 S2P_Bal_TypeLevel_63 "均衡等级";
CM_ SG_ 2417487487 S2P_Bal_SystemStatus_63 "均衡条件判断";
CM_ SG_ 2417487487 S2P_Bal_Strategy_63 "均衡策略";
CM_ SG_ 2417487487 S2P_Bal_ForceBalMode_63 "强制均衡模式";
CM_ SG_ 2417487487 S2P_Bal_CellTempFault_63 "温度单点无效";
CM_ SG_ 2417487487 S2P_Bal_CellVoltFail_63 "电芯电压采样失效";
CM_ SG_ 2417487487 S2P_Bal_CloseBalInstruct_63 "其他模块关闭均衡指令";
CM_ SG_ 2417487487 S2P_Bal_CCanTimeOut_63 "CCAN通讯超时故障";
CM_ SG_ 2417487487 S2P_Bal_CellOffLine_63 "预留";
CM_ SG_ 2417487487 S2P_Bal_BalanceCircuitFault_63 "均衡回路故障";
CM_ SG_ 2417487487 S2P_Bal_CSCSourceVoltFault_63 "CSC供电电压超限";
CM_ SG_ 2417487487 S2P_Bal_CellVoltOverFault_63 "预留";
CM_ SG_ 2417487487 S2P_Bal_CellVoltLowFault_63 "预留";
CM_ SG_ 2417487487 S2P_Bal_CSCPCBTempFault_63 "预留";
CM_ SG_ 2417487487 S2P_Bal_CSCSourceCurrLowFault_63 "CSC供电电流过低，禁止放电均衡";
CM_ SG_ 2417487487 S2P_Bal_CSCSourceCurrOvrFault_63 "CSC供电电流过高，禁止充电均衡";
CM_ SG_ 2416045633 S2P_DIAG_BYTE1_01 "SBMU发送到PC的诊断报文（详见SBMU MCAN调试协议）";
CM_ SG_ 2416045633 S2P_DIAG_BYTE2_01 "SBMU发送到PC的诊断报文（详见SBMU MCAN调试协议）";
CM_ SG_ 2416045633 S2P_DIAG_BYTE3_01 "SBMU发送到PC的诊断报文（详见SBMU MCAN调试协议）";
CM_ SG_ 2416045633 S2P_DIAG_BYTE4_01 "SBMU发送到PC的诊断报文（详见SBMU MCAN调试协议）";
CM_ SG_ 2416045633 S2P_DIAG_BYTE5_01 "SBMU发送到PC的诊断报文（详见SBMU MCAN调试协议）";
CM_ SG_ 2416045633 S2P_DIAG_BYTE6_01 "SBMU发送到PC的诊断报文（详见SBMU MCAN调试协议）";
CM_ SG_ 2416045633 S2P_DIAG_BYTE7_01 "SBMU发送到PC的诊断报文（详见SBMU MCAN调试协议）";
CM_ SG_ 2416045633 S2P_DIAG_BYTE8_01 "SBMU发送到PC的诊断报文（详见SBMU MCAN调试协议）";
CM_ SG_ 2416045634 S2P_DIAG_BYTE1_02 "SBMU发送到PC的诊断报文（详见SBMU MCAN调试协议）";
CM_ SG_ 2416045634 S2P_DIAG_BYTE2_02 "SBMU发送到PC的诊断报文（详见SBMU MCAN调试协议）";
CM_ SG_ 2416045634 S2P_DIAG_BYTE3_02 "SBMU发送到PC的诊断报文（详见SBMU MCAN调试协议）";
CM_ SG_ 2416045634 S2P_DIAG_BYTE4_02 "SBMU发送到PC的诊断报文（详见SBMU MCAN调试协议）";
CM_ SG_ 2416045634 S2P_DIAG_BYTE5_02 "SBMU发送到PC的诊断报文（详见SBMU MCAN调试协议）";
CM_ SG_ 2416045634 S2P_DIAG_BYTE6_02 "SBMU发送到PC的诊断报文（详见SBMU MCAN调试协议）";
CM_ SG_ 2416045634 S2P_DIAG_BYTE7_02 "SBMU发送到PC的诊断报文（详见SBMU MCAN调试协议）";
CM_ SG_ 2416045634 S2P_DIAG_BYTE8_02 "SBMU发送到PC的诊断报文（详见SBMU MCAN调试协议）";
CM_ SG_ 2416045635 S2P_DIAG_BYTE1_03 "SBMU发送到PC的诊断报文（详见SBMU MCAN调试协议）";
CM_ SG_ 2416045635 S2P_DIAG_BYTE2_03 "SBMU发送到PC的诊断报文（详见SBMU MCAN调试协议）";
CM_ SG_ 2416045635 S2P_DIAG_BYTE3_03 "SBMU发送到PC的诊断报文（详见SBMU MCAN调试协议）";
CM_ SG_ 2416045635 S2P_DIAG_BYTE4_03 "SBMU发送到PC的诊断报文（详见SBMU MCAN调试协议）";
CM_ SG_ 2416045635 S2P_DIAG_BYTE5_03 "SBMU发送到PC的诊断报文（详见SBMU MCAN调试协议）";
CM_ SG_ 2416045635 S2P_DIAG_BYTE6_03 "SBMU发送到PC的诊断报文（详见SBMU MCAN调试协议）";
CM_ SG_ 2416045635 S2P_DIAG_BYTE7_03 "SBMU发送到PC的诊断报文（详见SBMU MCAN调试协议）";
CM_ SG_ 2416045635 S2P_DIAG_BYTE8_03 "SBMU发送到PC的诊断报文（详见SBMU MCAN调试协议）";
CM_ SG_ 2416045636 S2P_DIAG_BYTE1_04 "SBMU发送到PC的诊断报文（详见SBMU MCAN调试协议）";
CM_ SG_ 2416045636 S2P_DIAG_BYTE2_04 "SBMU发送到PC的诊断报文（详见SBMU MCAN调试协议）";
CM_ SG_ 2416045636 S2P_DIAG_BYTE3_04 "SBMU发送到PC的诊断报文（详见SBMU MCAN调试协议）";
CM_ SG_ 2416045636 S2P_DIAG_BYTE4_04 "SBMU发送到PC的诊断报文（详见SBMU MCAN调试协议）";
CM_ SG_ 2416045636 S2P_DIAG_BYTE5_04 "SBMU发送到PC的诊断报文（详见SBMU MCAN调试协议）";
CM_ SG_ 2416045636 S2P_DIAG_BYTE6_04 "SBMU发送到PC的诊断报文（详见SBMU MCAN调试协议）";
CM_ SG_ 2416045636 S2P_DIAG_BYTE7_04 "SBMU发送到PC的诊断报文（详见SBMU MCAN调试协议）";
CM_ SG_ 2416045636 S2P_DIAG_BYTE8_04 "SBMU发送到PC的诊断报文（详见SBMU MCAN调试协议）";
VAL_ 2417487446 S2P_Bal_CSCNum_22 0 "No CSC" 1 "CSC 1" 2 "CSC 2" 3 "CSC 3" 4 "CSC 4" 5 "CSC 5" 6 "CSC 6" 7 "CSC 7" 8 "CSC 8" 9 "CSC 9" 10 "CSC 10" 11 "CSC 11" 12 "CSC 12" 13 "CSC 13" 14 "CSC 14" 15 "CSC 15" 16 "CSC 16" 17 "CSC 17" 18 "CSC 18" 19 "CSC 19" 20 "CSC 20" 21 "CSC 21" 22 "CSC 22" 23 "CSC 23" 24 "CSC 24" 25 "CSC 25" 26 "CSC 26" 27 "CSC 27" 28 "CSC 28" 29 "CSC 29" 30 "CSC 30" 31 "CSC 31" ;
VAL_ 2417487446 S2P_Bal_CellNum_22 1 "Cell 1" 2 "Cell 2" 3 "Cell 3" 4 "Cell 4" 5 "Cell 5" 6 "Cell 6" 7 "Cell 7" 8 "Cell 8" 9 "Cell 9" 10 "Cell 10" 11 "Cell 11" 12 "Cell 12" 13 "Cell 13" 14 "Cell 14" 15 "Cell 15" 16 "Cell 16" 63 "Null" ;
VAL_ 2417487446 S2P_Bal_Type_22 0 "Balance stop" 1 "charge Balance" 2 "discharge Balance" ;
VAL_ 2417487446 S2P_Bal_TypeLevel_22 0 "Not Balance" 1 "Low end Balance" 2 "High end Balance" 3 "Force Balance" ;
VAL_ 2417487446 S2P_Bal_SystemStatus_22 0 "Not Static" 1 "Staic Balance" 2 "Discharge false Balance" ;
VAL_ 2417487446 S2P_Bal_Strategy_22 0 "Active Balance" 1 "Passive Static" ;
VAL_ 2417487446 S2P_Bal_ForceBalMode_22 1 "Base on time " 2 "Base on Target Vol" 3 "Base on Ave Vol" ;
VAL_ 2417487446 S2P_Bal_CellTempFault_22 0 "Nomal" 1 "Fault" ;
VAL_ 2417487446 S2P_Bal_CellVoltFail_22 0 "Nomal" 1 "Fault" ;
VAL_ 2417487446 S2P_Bal_CloseBalInstruct_22 0 "Nomal" 1 "Fault" ;
VAL_ 2417487446 S2P_Bal_CCanTimeOut_22 0 "Nomal" 1 "Fault" ;
VAL_ 2417487446 S2P_Bal_CellOffLine_22 0 "Nomal" 1 "Fault" ;
VAL_ 2417487446 S2P_Bal_BalanceCircuitFault_22 0 "Nomal" 1 "Fault" ;
VAL_ 2417487446 S2P_Bal_CSCSourceVoltFault_22 0 "Nomal" 1 "Fault" ;
VAL_ 2417487446 S2P_Bal_CellVoltOverFault_22 0 "Nomal" 1 "Fault" ;
VAL_ 2417487446 S2P_Bal_CellVoltLowFault_22 0 "Nomal" 1 "Fault" ;
VAL_ 2417487446 S2P_Bal_CSCPCBTempFault_22 0 "Nomal" 1 "Fault" ;
VAL_ 2417487446 S2P_Bal_CSCSourceCurrLowFault_22 0 "Nomal" 1 "Fault" ;
VAL_ 2417487446 S2P_Bal_CSCSourceCurrOvrFault_22 0 "Nomal" 1 "Fault" ;
VAL_ 2417487447 S2P_Bal_CSCNum_23 0 "No CSC" 1 "CSC 1" 2 "CSC 2" 3 "CSC 3" 4 "CSC 4" 5 "CSC 5" 6 "CSC 6" 7 "CSC 7" 8 "CSC 8" 9 "CSC 9" 10 "CSC 10" 11 "CSC 11" 12 "CSC 12" 13 "CSC 13" 14 "CSC 14" 15 "CSC 15" 16 "CSC 16" 17 "CSC 17" 18 "CSC 18" 19 "CSC 19" 20 "CSC 20" 21 "CSC 21" 22 "CSC 22" 23 "CSC 23" 24 "CSC 24" 25 "CSC 25" 26 "CSC 26" 27 "CSC 27" 28 "CSC 28" 29 "CSC 29" 30 "CSC 30" 31 "CSC 31" ;
VAL_ 2417487447 S2P_Bal_CellNum_23 1 "Cell 1" 2 "Cell 2" 3 "Cell 3" 4 "Cell 4" 5 "Cell 5" 6 "Cell 6" 7 "Cell 7" 8 "Cell 8" 9 "Cell 9" 10 "Cell 10" 11 "Cell 11" 12 "Cell 12" 13 "Cell 13" 14 "Cell 14" 15 "Cell 15" 16 "Cell 16" 63 "Null" ;
VAL_ 2417487447 S2P_Bal_Type_23 0 "Balance stop" 1 "charge Balance" 2 "discharge Balance" ;
VAL_ 2417487447 S2P_Bal_TypeLevel_23 0 "Not Balance" 1 "Low end Balance" 2 "High end Balance" 3 "Force Balance" ;
VAL_ 2417487447 S2P_Bal_SystemStatus_23 0 "Not Static" 1 "Staic Balance" 2 "Discharge false Balance" ;
VAL_ 2417487447 S2P_Bal_Strategy_23 0 "Active Balance" 1 "Passive Static" ;
VAL_ 2417487447 S2P_Bal_ForceBalMode_23 1 "Base on time " 2 "Base on Target Vol" 3 "Base on Ave Vol" ;
VAL_ 2417487447 S2P_Bal_CellTempFault_23 0 "Nomal" 1 "Fault" ;
VAL_ 2417487447 S2P_Bal_CellVoltFail_23 0 "Nomal" 1 "Fault" ;
VAL_ 2417487447 S2P_Bal_CloseBalInstruct_23 0 "Nomal" 1 "Fault" ;
VAL_ 2417487447 S2P_Bal_CCanTimeOut_23 0 "Nomal" 1 "Fault" ;
VAL_ 2417487447 S2P_Bal_CellOffLine_23 0 "Nomal" 1 "Fault" ;
VAL_ 2417487447 S2P_Bal_BalanceCircuitFault_23 0 "Nomal" 1 "Fault" ;
VAL_ 2417487447 S2P_Bal_CSCSourceVoltFault_23 0 "Nomal" 1 "Fault" ;
VAL_ 2417487447 S2P_Bal_CellVoltOverFault_23 0 "Nomal" 1 "Fault" ;
VAL_ 2417487447 S2P_Bal_CellVoltLowFault_23 0 "Nomal" 1 "Fault" ;
VAL_ 2417487447 S2P_Bal_CSCPCBTempFault_23 0 "Nomal" 1 "Fault" ;
VAL_ 2417487447 S2P_Bal_CSCSourceCurrLowFault_23 0 "Nomal" 1 "Fault" ;
VAL_ 2417487447 S2P_Bal_CSCSourceCurrOvrFault_23 0 "Nomal" 1 "Fault" ;
VAL_ 2417487448 S2P_Bal_CSCNum_24 0 "No CSC" 1 "CSC 1" 2 "CSC 2" 3 "CSC 3" 4 "CSC 4" 5 "CSC 5" 6 "CSC 6" 7 "CSC 7" 8 "CSC 8" 9 "CSC 9" 10 "CSC 10" 11 "CSC 11" 12 "CSC 12" 13 "CSC 13" 14 "CSC 14" 15 "CSC 15" 16 "CSC 16" 17 "CSC 17" 18 "CSC 18" 19 "CSC 19" 20 "CSC 20" 21 "CSC 21" 22 "CSC 22" 23 "CSC 23" 24 "CSC 24" 25 "CSC 25" 26 "CSC 26" 27 "CSC 27" 28 "CSC 28" 29 "CSC 29" 30 "CSC 30" 31 "CSC 31" ;
VAL_ 2417487448 S2P_Bal_CellNum_24 1 "Cell 1" 2 "Cell 2" 3 "Cell 3" 4 "Cell 4" 5 "Cell 5" 6 "Cell 6" 7 "Cell 7" 8 "Cell 8" 9 "Cell 9" 10 "Cell 10" 11 "Cell 11" 12 "Cell 12" 13 "Cell 13" 14 "Cell 14" 15 "Cell 15" 16 "Cell 16" 63 "Null" ;
VAL_ 2417487448 S2P_Bal_Type_24 0 "Balance stop" 1 "charge Balance" 2 "discharge Balance" ;
VAL_ 2417487448 S2P_Bal_TypeLevel_24 0 "Not Balance" 1 "Low end Balance" 2 "High end Balance" 3 "Force Balance" ;
VAL_ 2417487448 S2P_Bal_SystemStatus_24 0 "Not Static" 1 "Staic Balance" 2 "Discharge false Balance" ;
VAL_ 2417487448 S2P_Bal_Strategy_24 0 "Active Balance" 1 "Passive Static" ;
VAL_ 2417487448 S2P_Bal_ForceBalMode_24 1 "Base on time " 2 "Base on Target Vol" 3 "Base on Ave Vol" ;
VAL_ 2417487448 S2P_Bal_CellTempFault_24 0 "Nomal" 1 "Fault" ;
VAL_ 2417487448 S2P_Bal_CellVoltFail_24 0 "Nomal" 1 "Fault" ;
VAL_ 2417487448 S2P_Bal_CloseBalInstruct_24 0 "Nomal" 1 "Fault" ;
VAL_ 2417487448 S2P_Bal_CCanTimeOut_24 0 "Nomal" 1 "Fault" ;
VAL_ 2417487448 S2P_Bal_CellOffLine_24 0 "Nomal" 1 "Fault" ;
VAL_ 2417487448 S2P_Bal_BalanceCircuitFault_24 0 "Nomal" 1 "Fault" ;
VAL_ 2417487448 S2P_Bal_CSCSourceVoltFault_24 0 "Nomal" 1 "Fault" ;
VAL_ 2417487448 S2P_Bal_CellVoltOverFault_24 0 "Nomal" 1 "Fault" ;
VAL_ 2417487448 S2P_Bal_CellVoltLowFault_24 0 "Nomal" 1 "Fault" ;
VAL_ 2417487448 S2P_Bal_CSCPCBTempFault_24 0 "Nomal" 1 "Fault" ;
VAL_ 2417487448 S2P_Bal_CSCSourceCurrLowFault_24 0 "Nomal" 1 "Fault" ;
VAL_ 2417487448 S2P_Bal_CSCSourceCurrOvrFault_24 0 "Nomal" 1 "Fault" ;
VAL_ 2417487449 S2P_Bal_CSCNum_25 0 "No CSC" 1 "CSC 1" 2 "CSC 2" 3 "CSC 3" 4 "CSC 4" 5 "CSC 5" 6 "CSC 6" 7 "CSC 7" 8 "CSC 8" 9 "CSC 9" 10 "CSC 10" 11 "CSC 11" 12 "CSC 12" 13 "CSC 13" 14 "CSC 14" 15 "CSC 15" 16 "CSC 16" 17 "CSC 17" 18 "CSC 18" 19 "CSC 19" 20 "CSC 20" 21 "CSC 21" 22 "CSC 22" 23 "CSC 23" 24 "CSC 24" 25 "CSC 25" 26 "CSC 26" 27 "CSC 27" 28 "CSC 28" 29 "CSC 29" 30 "CSC 30" 31 "CSC 31" ;
VAL_ 2417487449 S2P_Bal_CellNum_25 1 "Cell 1" 2 "Cell 2" 3 "Cell 3" 4 "Cell 4" 5 "Cell 5" 6 "Cell 6" 7 "Cell 7" 8 "Cell 8" 9 "Cell 9" 10 "Cell 10" 11 "Cell 11" 12 "Cell 12" 13 "Cell 13" 14 "Cell 14" 15 "Cell 15" 16 "Cell 16" 63 "Null" ;
VAL_ 2417487449 S2P_Bal_Type_25 0 "Balance stop" 1 "charge Balance" 2 "discharge Balance" ;
VAL_ 2417487449 S2P_Bal_TypeLevel_25 0 "Not Balance" 1 "Low end Balance" 2 "High end Balance" 3 "Force Balance" ;
VAL_ 2417487449 S2P_Bal_SystemStatus_25 0 "Not Static" 1 "Staic Balance" 2 "Discharge false Balance" ;
VAL_ 2417487449 S2P_Bal_Strategy_25 0 "Active Balance" 1 "Passive Static" ;
VAL_ 2417487449 S2P_Bal_ForceBalMode_25 1 "Base on time " 2 "Base on Target Vol" 3 "Base on Ave Vol" ;
VAL_ 2417487449 S2P_Bal_CellTempFault_25 0 "Nomal" 1 "Fault" ;
VAL_ 2417487449 S2P_Bal_CellVoltFail_25 0 "Nomal" 1 "Fault" ;
VAL_ 2417487449 S2P_Bal_CloseBalInstruct_25 0 "Nomal" 1 "Fault" ;
VAL_ 2417487449 S2P_Bal_CCanTimeOut_25 0 "Nomal" 1 "Fault" ;
VAL_ 2417487449 S2P_Bal_CellOffLine_25 0 "Nomal" 1 "Fault" ;
VAL_ 2417487449 S2P_Bal_BalanceCircuitFault_25 0 "Nomal" 1 "Fault" ;
VAL_ 2417487449 S2P_Bal_CSCSourceVoltFault_25 0 "Nomal" 1 "Fault" ;
VAL_ 2417487449 S2P_Bal_CellVoltOverFault_25 0 "Nomal" 1 "Fault" ;
VAL_ 2417487449 S2P_Bal_CellVoltLowFault_25 0 "Nomal" 1 "Fault" ;
VAL_ 2417487449 S2P_Bal_CSCPCBTempFault_25 0 "Nomal" 1 "Fault" ;
VAL_ 2417487449 S2P_Bal_CSCSourceCurrLowFault_25 0 "Nomal" 1 "Fault" ;
VAL_ 2417487449 S2P_Bal_CSCSourceCurrOvrFault_25 0 "Nomal" 1 "Fault" ;
VAL_ 2417487450 S2P_Bal_CSCNum_26 0 "No CSC" 1 "CSC 1" 2 "CSC 2" 3 "CSC 3" 4 "CSC 4" 5 "CSC 5" 6 "CSC 6" 7 "CSC 7" 8 "CSC 8" 9 "CSC 9" 10 "CSC 10" 11 "CSC 11" 12 "CSC 12" 13 "CSC 13" 14 "CSC 14" 15 "CSC 15" 16 "CSC 16" 17 "CSC 17" 18 "CSC 18" 19 "CSC 19" 20 "CSC 20" 21 "CSC 21" 22 "CSC 22" 23 "CSC 23" 24 "CSC 24" 25 "CSC 25" 26 "CSC 26" 27 "CSC 27" 28 "CSC 28" 29 "CSC 29" 30 "CSC 30" 31 "CSC 31" ;
VAL_ 2417487450 S2P_Bal_CellNum_26 1 "Cell 1" 2 "Cell 2" 3 "Cell 3" 4 "Cell 4" 5 "Cell 5" 6 "Cell 6" 7 "Cell 7" 8 "Cell 8" 9 "Cell 9" 10 "Cell 10" 11 "Cell 11" 12 "Cell 12" 13 "Cell 13" 14 "Cell 14" 15 "Cell 15" 16 "Cell 16" 63 "Null" ;
VAL_ 2417487450 S2P_Bal_Type_26 0 "Balance stop" 1 "charge Balance" 2 "discharge Balance" ;
VAL_ 2417487450 S2P_Bal_TypeLevel_26 0 "Not Balance" 1 "Low end Balance" 2 "High end Balance" 3 "Force Balance" ;
VAL_ 2417487450 S2P_Bal_SystemStatus_26 0 "Not Static" 1 "Staic Balance" 2 "Discharge false Balance" ;
VAL_ 2417487450 S2P_Bal_Strategy_26 0 "Active Balance" 1 "Passive Static" ;
VAL_ 2417487450 S2P_Bal_ForceBalMode_26 1 "Base on time " 2 "Base on Target Vol" 3 "Base on Ave Vol" ;
VAL_ 2417487450 S2P_Bal_CellTempFault_26 0 "Nomal" 1 "Fault" ;
VAL_ 2417487450 S2P_Bal_CellVoltFail_26 0 "Nomal" 1 "Fault" ;
VAL_ 2417487450 S2P_Bal_CloseBalInstruct_26 0 "Nomal" 1 "Fault" ;
VAL_ 2417487450 S2P_Bal_CCanTimeOut_26 0 "Nomal" 1 "Fault" ;
VAL_ 2417487450 S2P_Bal_CellOffLine_26 0 "Nomal" 1 "Fault" ;
VAL_ 2417487450 S2P_Bal_BalanceCircuitFault_26 0 "Nomal" 1 "Fault" ;
VAL_ 2417487450 S2P_Bal_CSCSourceVoltFault_26 0 "Nomal" 1 "Fault" ;
VAL_ 2417487450 S2P_Bal_CellVoltOverFault_26 0 "Nomal" 1 "Fault" ;
VAL_ 2417487450 S2P_Bal_CellVoltLowFault_26 0 "Nomal" 1 "Fault" ;
VAL_ 2417487450 S2P_Bal_CSCPCBTempFault_26 0 "Nomal" 1 "Fault" ;
VAL_ 2417487450 S2P_Bal_CSCSourceCurrLowFault_26 0 "Nomal" 1 "Fault" ;
VAL_ 2417487450 S2P_Bal_CSCSourceCurrOvrFault_26 0 "Nomal" 1 "Fault" ;
VAL_ 2417487451 S2P_Bal_CSCNum_27 0 "No CSC" 1 "CSC 1" 2 "CSC 2" 3 "CSC 3" 4 "CSC 4" 5 "CSC 5" 6 "CSC 6" 7 "CSC 7" 8 "CSC 8" 9 "CSC 9" 10 "CSC 10" 11 "CSC 11" 12 "CSC 12" 13 "CSC 13" 14 "CSC 14" 15 "CSC 15" 16 "CSC 16" 17 "CSC 17" 18 "CSC 18" 19 "CSC 19" 20 "CSC 20" 21 "CSC 21" 22 "CSC 22" 23 "CSC 23" 24 "CSC 24" 25 "CSC 25" 26 "CSC 26" 27 "CSC 27" 28 "CSC 28" 29 "CSC 29" 30 "CSC 30" 31 "CSC 31" ;
VAL_ 2417487451 S2P_Bal_CellNum_27 1 "Cell 1" 2 "Cell 2" 3 "Cell 3" 4 "Cell 4" 5 "Cell 5" 6 "Cell 6" 7 "Cell 7" 8 "Cell 8" 9 "Cell 9" 10 "Cell 10" 11 "Cell 11" 12 "Cell 12" 13 "Cell 13" 14 "Cell 14" 15 "Cell 15" 16 "Cell 16" 63 "Null" ;
VAL_ 2417487451 S2P_Bal_Type_27 0 "Balance stop" 1 "charge Balance" 2 "discharge Balance" ;
VAL_ 2417487451 S2P_Bal_TypeLevel_27 0 "Not Balance" 1 "Low end Balance" 2 "High end Balance" 3 "Force Balance" ;
VAL_ 2417487451 S2P_Bal_SystemStatus_27 0 "Not Static" 1 "Staic Balance" 2 "Discharge false Balance" ;
VAL_ 2417487451 S2P_Bal_Strategy_27 0 "Active Balance" 1 "Passive Static" ;
VAL_ 2417487451 S2P_Bal_ForceBalMode_27 1 "Base on time " 2 "Base on Target Vol" 3 "Base on Ave Vol" ;
VAL_ 2417487451 S2P_Bal_CellTempFault_27 0 "Nomal" 1 "Fault" ;
VAL_ 2417487451 S2P_Bal_CellVoltFail_27 0 "Nomal" 1 "Fault" ;
VAL_ 2417487451 S2P_Bal_CloseBalInstruct_27 0 "Nomal" 1 "Fault" ;
VAL_ 2417487451 S2P_Bal_CCanTimeOut_27 0 "Nomal" 1 "Fault" ;
VAL_ 2417487451 S2P_Bal_CellOffLine_27 0 "Nomal" 1 "Fault" ;
VAL_ 2417487451 S2P_Bal_BalanceCircuitFault_27 0 "Nomal" 1 "Fault" ;
VAL_ 2417487451 S2P_Bal_CSCSourceVoltFault_27 0 "Nomal" 1 "Fault" ;
VAL_ 2417487451 S2P_Bal_CellVoltOverFault_27 0 "Nomal" 1 "Fault" ;
VAL_ 2417487451 S2P_Bal_CellVoltLowFault_27 0 "Nomal" 1 "Fault" ;
VAL_ 2417487451 S2P_Bal_CSCPCBTempFault_27 0 "Nomal" 1 "Fault" ;
VAL_ 2417487451 S2P_Bal_CSCSourceCurrLowFault_27 0 "Nomal" 1 "Fault" ;
VAL_ 2417487451 S2P_Bal_CSCSourceCurrOvrFault_27 0 "Nomal" 1 "Fault" ;
VAL_ 2417487452 S2P_Bal_CSCNum_28 0 "No CSC" 1 "CSC 1" 2 "CSC 2" 3 "CSC 3" 4 "CSC 4" 5 "CSC 5" 6 "CSC 6" 7 "CSC 7" 8 "CSC 8" 9 "CSC 9" 10 "CSC 10" 11 "CSC 11" 12 "CSC 12" 13 "CSC 13" 14 "CSC 14" 15 "CSC 15" 16 "CSC 16" 17 "CSC 17" 18 "CSC 18" 19 "CSC 19" 20 "CSC 20" 21 "CSC 21" 22 "CSC 22" 23 "CSC 23" 24 "CSC 24" 25 "CSC 25" 26 "CSC 26" 27 "CSC 27" 28 "CSC 28" 29 "CSC 29" 30 "CSC 30" 31 "CSC 31" ;
VAL_ 2417487452 S2P_Bal_CellNum_28 1 "Cell 1" 2 "Cell 2" 3 "Cell 3" 4 "Cell 4" 5 "Cell 5" 6 "Cell 6" 7 "Cell 7" 8 "Cell 8" 9 "Cell 9" 10 "Cell 10" 11 "Cell 11" 12 "Cell 12" 13 "Cell 13" 14 "Cell 14" 15 "Cell 15" 16 "Cell 16" 63 "Null" ;
VAL_ 2417487452 S2P_Bal_Type_28 0 "Balance stop" 1 "charge Balance" 2 "discharge Balance" ;
VAL_ 2417487452 S2P_Bal_TypeLevel_28 0 "Not Balance" 1 "Low end Balance" 2 "High end Balance" 3 "Force Balance" ;
VAL_ 2417487452 S2P_Bal_SystemStatus_28 0 "Not Static" 1 "Staic Balance" 2 "Discharge false Balance" ;
VAL_ 2417487452 S2P_Bal_Strategy_28 0 "Active Balance" 1 "Passive Static" ;
VAL_ 2417487452 S2P_Bal_ForceBalMode_28 1 "Base on time " 2 "Base on Target Vol" 3 "Base on Ave Vol" ;
VAL_ 2417487452 S2P_Bal_CellTempFault_28 0 "Nomal" 1 "Fault" ;
VAL_ 2417487452 S2P_Bal_CellVoltFail_28 0 "Nomal" 1 "Fault" ;
VAL_ 2417487452 S2P_Bal_CloseBalInstruct_28 0 "Nomal" 1 "Fault" ;
VAL_ 2417487452 S2P_Bal_CCanTimeOut_28 0 "Nomal" 1 "Fault" ;
VAL_ 2417487452 S2P_Bal_CellOffLine_28 0 "Nomal" 1 "Fault" ;
VAL_ 2417487452 S2P_Bal_BalanceCircuitFault_28 0 "Nomal" 1 "Fault" ;
VAL_ 2417487452 S2P_Bal_CSCSourceVoltFault_28 0 "Nomal" 1 "Fault" ;
VAL_ 2417487452 S2P_Bal_CellVoltOverFault_28 0 "Nomal" 1 "Fault" ;
VAL_ 2417487452 S2P_Bal_CellVoltLowFault_28 0 "Nomal" 1 "Fault" ;
VAL_ 2417487452 S2P_Bal_CSCPCBTempFault_28 0 "Nomal" 1 "Fault" ;
VAL_ 2417487452 S2P_Bal_CSCSourceCurrLowFault_28 0 "Nomal" 1 "Fault" ;
VAL_ 2417487452 S2P_Bal_CSCSourceCurrOvrFault_28 0 "Nomal" 1 "Fault" ;
VAL_ 2417487453 S2P_Bal_CSCNum_29 0 "No CSC" 1 "CSC 1" 2 "CSC 2" 3 "CSC 3" 4 "CSC 4" 5 "CSC 5" 6 "CSC 6" 7 "CSC 7" 8 "CSC 8" 9 "CSC 9" 10 "CSC 10" 11 "CSC 11" 12 "CSC 12" 13 "CSC 13" 14 "CSC 14" 15 "CSC 15" 16 "CSC 16" 17 "CSC 17" 18 "CSC 18" 19 "CSC 19" 20 "CSC 20" 21 "CSC 21" 22 "CSC 22" 23 "CSC 23" 24 "CSC 24" 25 "CSC 25" 26 "CSC 26" 27 "CSC 27" 28 "CSC 28" 29 "CSC 29" 30 "CSC 30" 31 "CSC 31" ;
VAL_ 2417487453 S2P_Bal_CellNum_29 1 "Cell 1" 2 "Cell 2" 3 "Cell 3" 4 "Cell 4" 5 "Cell 5" 6 "Cell 6" 7 "Cell 7" 8 "Cell 8" 9 "Cell 9" 10 "Cell 10" 11 "Cell 11" 12 "Cell 12" 13 "Cell 13" 14 "Cell 14" 15 "Cell 15" 16 "Cell 16" 63 "Null" ;
VAL_ 2417487453 S2P_Bal_Type_29 0 "Balance stop" 1 "charge Balance" 2 "discharge Balance" ;
VAL_ 2417487453 S2P_Bal_TypeLevel_29 0 "Not Balance" 1 "Low end Balance" 2 "High end Balance" 3 "Force Balance" ;
VAL_ 2417487453 S2P_Bal_SystemStatus_29 0 "Not Static" 1 "Staic Balance" 2 "Discharge false Balance" ;
VAL_ 2417487453 S2P_Bal_Strategy_29 0 "Active Balance" 1 "Passive Static" ;
VAL_ 2417487453 S2P_Bal_ForceBalMode_29 1 "Base on time " 2 "Base on Target Vol" 3 "Base on Ave Vol" ;
VAL_ 2417487453 S2P_Bal_CellTempFault_29 0 "Nomal" 1 "Fault" ;
VAL_ 2417487453 S2P_Bal_CellVoltFail_29 0 "Nomal" 1 "Fault" ;
VAL_ 2417487453 S2P_Bal_CloseBalInstruct_29 0 "Nomal" 1 "Fault" ;
VAL_ 2417487453 S2P_Bal_CCanTimeOut_29 0 "Nomal" 1 "Fault" ;
VAL_ 2417487453 S2P_Bal_CellOffLine_29 0 "Nomal" 1 "Fault" ;
VAL_ 2417487453 S2P_Bal_BalanceCircuitFault_29 0 "Nomal" 1 "Fault" ;
VAL_ 2417487453 S2P_Bal_CSCSourceVoltFault_29 0 "Nomal" 1 "Fault" ;
VAL_ 2417487453 S2P_Bal_CellVoltOverFault_29 0 "Nomal" 1 "Fault" ;
VAL_ 2417487453 S2P_Bal_CellVoltLowFault_29 0 "Nomal" 1 "Fault" ;
VAL_ 2417487453 S2P_Bal_CSCPCBTempFault_29 0 "Nomal" 1 "Fault" ;
VAL_ 2417487453 S2P_Bal_CSCSourceCurrLowFault_29 0 "Nomal" 1 "Fault" ;
VAL_ 2417487453 S2P_Bal_CSCSourceCurrOvrFault_29 0 "Nomal" 1 "Fault" ;
VAL_ 2417487454 S2P_Bal_CSCNum_30 0 "No CSC" 1 "CSC 1" 2 "CSC 2" 3 "CSC 3" 4 "CSC 4" 5 "CSC 5" 6 "CSC 6" 7 "CSC 7" 8 "CSC 8" 9 "CSC 9" 10 "CSC 10" 11 "CSC 11" 12 "CSC 12" 13 "CSC 13" 14 "CSC 14" 15 "CSC 15" 16 "CSC 16" 17 "CSC 17" 18 "CSC 18" 19 "CSC 19" 20 "CSC 20" 21 "CSC 21" 22 "CSC 22" 23 "CSC 23" 24 "CSC 24" 25 "CSC 25" 26 "CSC 26" 27 "CSC 27" 28 "CSC 28" 29 "CSC 29" 30 "CSC 30" 31 "CSC 31" ;
VAL_ 2417487454 S2P_Bal_CellNum_30 1 "Cell 1" 2 "Cell 2" 3 "Cell 3" 4 "Cell 4" 5 "Cell 5" 6 "Cell 6" 7 "Cell 7" 8 "Cell 8" 9 "Cell 9" 10 "Cell 10" 11 "Cell 11" 12 "Cell 12" 13 "Cell 13" 14 "Cell 14" 15 "Cell 15" 16 "Cell 16" 63 "Null" ;
VAL_ 2417487454 S2P_Bal_Type_30 0 "Balance stop" 1 "charge Balance" 2 "discharge Balance" ;
VAL_ 2417487454 S2P_Bal_TypeLevel_30 0 "Not Balance" 1 "Low end Balance" 2 "High end Balance" 3 "Force Balance" ;
VAL_ 2417487454 S2P_Bal_SystemStatus_30 0 "Not Static" 1 "Staic Balance" 2 "Discharge false Balance" ;
VAL_ 2417487454 S2P_Bal_Strategy_30 0 "Active Balance" 1 "Passive Static" ;
VAL_ 2417487454 S2P_Bal_ForceBalMode_30 1 "Base on time " 2 "Base on Target Vol" 3 "Base on Ave Vol" ;
VAL_ 2417487454 S2P_Bal_CellTempFault_30 0 "Nomal" 1 "Fault" ;
VAL_ 2417487454 S2P_Bal_CellVoltFail_30 0 "Nomal" 1 "Fault" ;
VAL_ 2417487454 S2P_Bal_CloseBalInstruct_30 0 "Nomal" 1 "Fault" ;
VAL_ 2417487454 S2P_Bal_CCanTimeOut_30 0 "Nomal" 1 "Fault" ;
VAL_ 2417487454 S2P_Bal_CellOffLine_30 0 "Nomal" 1 "Fault" ;
VAL_ 2417487454 S2P_Bal_BalanceCircuitFault_30 0 "Nomal" 1 "Fault" ;
VAL_ 2417487454 S2P_Bal_CSCSourceVoltFault_30 0 "Nomal" 1 "Fault" ;
VAL_ 2417487454 S2P_Bal_CellVoltOverFault_30 0 "Nomal" 1 "Fault" ;
VAL_ 2417487454 S2P_Bal_CellVoltLowFault_30 0 "Nomal" 1 "Fault" ;
VAL_ 2417487454 S2P_Bal_CSCPCBTempFault_30 0 "Nomal" 1 "Fault" ;
VAL_ 2417487454 S2P_Bal_CSCSourceCurrLowFault_30 0 "Nomal" 1 "Fault" ;
VAL_ 2417487454 S2P_Bal_CSCSourceCurrOvrFault_30 0 "Nomal" 1 "Fault" ;
VAL_ 2417487455 S2P_Bal_CSCNum_31 0 "No CSC" 1 "CSC 1" 2 "CSC 2" 3 "CSC 3" 4 "CSC 4" 5 "CSC 5" 6 "CSC 6" 7 "CSC 7" 8 "CSC 8" 9 "CSC 9" 10 "CSC 10" 11 "CSC 11" 12 "CSC 12" 13 "CSC 13" 14 "CSC 14" 15 "CSC 15" 16 "CSC 16" 17 "CSC 17" 18 "CSC 18" 19 "CSC 19" 20 "CSC 20" 21 "CSC 21" 22 "CSC 22" 23 "CSC 23" 24 "CSC 24" 25 "CSC 25" 26 "CSC 26" 27 "CSC 27" 28 "CSC 28" 29 "CSC 29" 30 "CSC 30" 31 "CSC 31" ;
VAL_ 2417487455 S2P_Bal_CellNum_31 1 "Cell 1" 2 "Cell 2" 3 "Cell 3" 4 "Cell 4" 5 "Cell 5" 6 "Cell 6" 7 "Cell 7" 8 "Cell 8" 9 "Cell 9" 10 "Cell 10" 11 "Cell 11" 12 "Cell 12" 13 "Cell 13" 14 "Cell 14" 15 "Cell 15" 16 "Cell 16" 63 "Null" ;
VAL_ 2417487455 S2P_Bal_Type_31 0 "Balance stop" 1 "charge Balance" 2 "discharge Balance" ;
VAL_ 2417487455 S2P_Bal_TypeLevel_31 0 "Not Balance" 1 "Low end Balance" 2 "High end Balance" 3 "Force Balance" ;
VAL_ 2417487455 S2P_Bal_SystemStatus_31 0 "Not Static" 1 "Staic Balance" 2 "Discharge false Balance" ;
VAL_ 2417487455 S2P_Bal_Strategy_31 0 "Active Balance" 1 "Passive Static" ;
VAL_ 2417487455 S2P_Bal_ForceBalMode_31 1 "Base on time " 2 "Base on Target Vol" 3 "Base on Ave Vol" ;
VAL_ 2417487455 S2P_Bal_CellTempFault_31 0 "Nomal" 1 "Fault" ;
VAL_ 2417487455 S2P_Bal_CellVoltFail_31 0 "Nomal" 1 "Fault" ;
VAL_ 2417487455 S2P_Bal_CloseBalInstruct_31 0 "Nomal" 1 "Fault" ;
VAL_ 2417487455 S2P_Bal_CCanTimeOut_31 0 "Nomal" 1 "Fault" ;
VAL_ 2417487455 S2P_Bal_CellOffLine_31 0 "Nomal" 1 "Fault" ;
VAL_ 2417487455 S2P_Bal_BalanceCircuitFault_31 0 "Nomal" 1 "Fault" ;
VAL_ 2417487455 S2P_Bal_CSCSourceVoltFault_31 0 "Nomal" 1 "Fault" ;
VAL_ 2417487455 S2P_Bal_CellVoltOverFault_31 0 "Nomal" 1 "Fault" ;
VAL_ 2417487455 S2P_Bal_CellVoltLowFault_31 0 "Nomal" 1 "Fault" ;
VAL_ 2417487455 S2P_Bal_CSCPCBTempFault_31 0 "Nomal" 1 "Fault" ;
VAL_ 2417487455 S2P_Bal_CSCSourceCurrLowFault_31 0 "Nomal" 1 "Fault" ;
VAL_ 2417487455 S2P_Bal_CSCSourceCurrOvrFault_31 0 "Nomal" 1 "Fault" ;
VAL_ 2417487456 S2P_Bal_CSCNum_32 0 "No CSC" 1 "CSC 1" 2 "CSC 2" 3 "CSC 3" 4 "CSC 4" 5 "CSC 5" 6 "CSC 6" 7 "CSC 7" 8 "CSC 8" 9 "CSC 9" 10 "CSC 10" 11 "CSC 11" 12 "CSC 12" 13 "CSC 13" 14 "CSC 14" 15 "CSC 15" 16 "CSC 16" 17 "CSC 17" 18 "CSC 18" 19 "CSC 19" 20 "CSC 20" 21 "CSC 21" 22 "CSC 22" 23 "CSC 23" 24 "CSC 24" 25 "CSC 25" 26 "CSC 26" 27 "CSC 27" 28 "CSC 28" 29 "CSC 29" 30 "CSC 30" 31 "CSC 31" ;
VAL_ 2417487456 S2P_Bal_CellNum_32 1 "Cell 1" 2 "Cell 2" 3 "Cell 3" 4 "Cell 4" 5 "Cell 5" 6 "Cell 6" 7 "Cell 7" 8 "Cell 8" 9 "Cell 9" 10 "Cell 10" 11 "Cell 11" 12 "Cell 12" 13 "Cell 13" 14 "Cell 14" 15 "Cell 15" 16 "Cell 16" 63 "Null" ;
VAL_ 2417487456 S2P_Bal_Type_32 0 "Balance stop" 1 "charge Balance" 2 "discharge Balance" ;
VAL_ 2417487456 S2P_Bal_TypeLevel_32 0 "Not Balance" 1 "Low end Balance" 2 "High end Balance" 3 "Force Balance" ;
VAL_ 2417487456 S2P_Bal_SystemStatus_32 0 "Not Static" 1 "Staic Balance" 2 "Discharge false Balance" ;
VAL_ 2417487456 S2P_Bal_Strategy_32 0 "Active Balance" 1 "Passive Static" ;
VAL_ 2417487456 S2P_Bal_ForceBalMode_32 1 "Base on time " 2 "Base on Target Vol" 3 "Base on Ave Vol" ;
VAL_ 2417487456 S2P_Bal_CellTempFault_32 0 "Nomal" 1 "Fault" ;
VAL_ 2417487456 S2P_Bal_CellVoltFail_32 0 "Nomal" 1 "Fault" ;
VAL_ 2417487456 S2P_Bal_CloseBalInstruct_32 0 "Nomal" 1 "Fault" ;
VAL_ 2417487456 S2P_Bal_CCanTimeOut_32 0 "Nomal" 1 "Fault" ;
VAL_ 2417487456 S2P_Bal_CellOffLine_32 0 "Nomal" 1 "Fault" ;
VAL_ 2417487456 S2P_Bal_BalanceCircuitFault_32 0 "Nomal" 1 "Fault" ;
VAL_ 2417487456 S2P_Bal_CSCSourceVoltFault_32 0 "Nomal" 1 "Fault" ;
VAL_ 2417487456 S2P_Bal_CellVoltOverFault_32 0 "Nomal" 1 "Fault" ;
VAL_ 2417487456 S2P_Bal_CellVoltLowFault_32 0 "Nomal" 1 "Fault" ;
VAL_ 2417487456 S2P_Bal_CSCPCBTempFault_32 0 "Nomal" 1 "Fault" ;
VAL_ 2417487456 S2P_Bal_CSCSourceCurrLowFault_32 0 "Nomal" 1 "Fault" ;
VAL_ 2417487456 S2P_Bal_CSCSourceCurrOvrFault_32 0 "Nomal" 1 "Fault" ;
VAL_ 2417487457 S2P_Bal_CSCNum_33 0 "No CSC" 1 "CSC 1" 2 "CSC 2" 3 "CSC 3" 4 "CSC 4" 5 "CSC 5" 6 "CSC 6" 7 "CSC 7" 8 "CSC 8" 9 "CSC 9" 10 "CSC 10" 11 "CSC 11" 12 "CSC 12" 13 "CSC 13" 14 "CSC 14" 15 "CSC 15" 16 "CSC 16" 17 "CSC 17" 18 "CSC 18" 19 "CSC 19" 20 "CSC 20" 21 "CSC 21" 22 "CSC 22" 23 "CSC 23" 24 "CSC 24" 25 "CSC 25" 26 "CSC 26" 27 "CSC 27" 28 "CSC 28" 29 "CSC 29" 30 "CSC 30" 31 "CSC 31" ;
VAL_ 2417487457 S2P_Bal_CellNum_33 1 "Cell 1" 2 "Cell 2" 3 "Cell 3" 4 "Cell 4" 5 "Cell 5" 6 "Cell 6" 7 "Cell 7" 8 "Cell 8" 9 "Cell 9" 10 "Cell 10" 11 "Cell 11" 12 "Cell 12" 13 "Cell 13" 14 "Cell 14" 15 "Cell 15" 16 "Cell 16" 63 "Null" ;
VAL_ 2417487457 S2P_Bal_Type_33 0 "Balance stop" 1 "charge Balance" 2 "discharge Balance" ;
VAL_ 2417487457 S2P_Bal_TypeLevel_33 0 "Not Balance" 1 "Low end Balance" 2 "High end Balance" 3 "Force Balance" ;
VAL_ 2417487457 S2P_Bal_SystemStatus_33 0 "Not Static" 1 "Staic Balance" 2 "Discharge false Balance" ;
VAL_ 2417487457 S2P_Bal_Strategy_33 0 "Active Balance" 1 "Passive Static" ;
VAL_ 2417487457 S2P_Bal_ForceBalMode_33 1 "Base on time " 2 "Base on Target Vol" 3 "Base on Ave Vol" ;
VAL_ 2417487457 S2P_Bal_CellTempFault_33 0 "Nomal" 1 "Fault" ;
VAL_ 2417487457 S2P_Bal_CellVoltFail_33 0 "Nomal" 1 "Fault" ;
VAL_ 2417487457 S2P_Bal_CloseBalInstruct_33 0 "Nomal" 1 "Fault" ;
VAL_ 2417487457 S2P_Bal_CCanTimeOut_33 0 "Nomal" 1 "Fault" ;
VAL_ 2417487457 S2P_Bal_CellOffLine_33 0 "Nomal" 1 "Fault" ;
VAL_ 2417487457 S2P_Bal_BalanceCircuitFault_33 0 "Nomal" 1 "Fault" ;
VAL_ 2417487457 S2P_Bal_CSCSourceVoltFault_33 0 "Nomal" 1 "Fault" ;
VAL_ 2417487457 S2P_Bal_CellVoltOverFault_33 0 "Nomal" 1 "Fault" ;
VAL_ 2417487457 S2P_Bal_CellVoltLowFault_33 0 "Nomal" 1 "Fault" ;
VAL_ 2417487457 S2P_Bal_CSCPCBTempFault_33 0 "Nomal" 1 "Fault" ;
VAL_ 2417487457 S2P_Bal_CSCSourceCurrLowFault_33 0 "Nomal" 1 "Fault" ;
VAL_ 2417487457 S2P_Bal_CSCSourceCurrOvrFault_33 0 "Nomal" 1 "Fault" ;
VAL_ 2417487458 S2P_Bal_CSCNum_34 0 "No CSC" 1 "CSC 1" 2 "CSC 2" 3 "CSC 3" 4 "CSC 4" 5 "CSC 5" 6 "CSC 6" 7 "CSC 7" 8 "CSC 8" 9 "CSC 9" 10 "CSC 10" 11 "CSC 11" 12 "CSC 12" 13 "CSC 13" 14 "CSC 14" 15 "CSC 15" 16 "CSC 16" 17 "CSC 17" 18 "CSC 18" 19 "CSC 19" 20 "CSC 20" 21 "CSC 21" 22 "CSC 22" 23 "CSC 23" 24 "CSC 24" 25 "CSC 25" 26 "CSC 26" 27 "CSC 27" 28 "CSC 28" 29 "CSC 29" 30 "CSC 30" 31 "CSC 31" ;
VAL_ 2417487458 S2P_Bal_CellNum_34 1 "Cell 1" 2 "Cell 2" 3 "Cell 3" 4 "Cell 4" 5 "Cell 5" 6 "Cell 6" 7 "Cell 7" 8 "Cell 8" 9 "Cell 9" 10 "Cell 10" 11 "Cell 11" 12 "Cell 12" 13 "Cell 13" 14 "Cell 14" 15 "Cell 15" 16 "Cell 16" 63 "Null" ;
VAL_ 2417487458 S2P_Bal_Type_34 0 "Balance stop" 1 "charge Balance" 2 "discharge Balance" ;
VAL_ 2417487458 S2P_Bal_TypeLevel_34 0 "Not Balance" 1 "Low end Balance" 2 "High end Balance" 3 "Force Balance" ;
VAL_ 2417487458 S2P_Bal_SystemStatus_34 0 "Not Static" 1 "Staic Balance" 2 "Discharge false Balance" ;
VAL_ 2417487458 S2P_Bal_Strategy_34 0 "Active Balance" 1 "Passive Static" ;
VAL_ 2417487458 S2P_Bal_ForceBalMode_34 1 "Base on time " 2 "Base on Target Vol" 3 "Base on Ave Vol" ;
VAL_ 2417487458 S2P_Bal_CellTempFault_34 0 "Nomal" 1 "Fault" ;
VAL_ 2417487458 S2P_Bal_CellVoltFail_34 0 "Nomal" 1 "Fault" ;
VAL_ 2417487458 S2P_Bal_CloseBalInstruct_34 0 "Nomal" 1 "Fault" ;
VAL_ 2417487458 S2P_Bal_CCanTimeOut_34 0 "Nomal" 1 "Fault" ;
VAL_ 2417487458 S2P_Bal_CellOffLine_34 0 "Nomal" 1 "Fault" ;
VAL_ 2417487458 S2P_Bal_BalanceCircuitFault_34 0 "Nomal" 1 "Fault" ;
VAL_ 2417487458 S2P_Bal_CSCSourceVoltFault_34 0 "Nomal" 1 "Fault" ;
VAL_ 2417487458 S2P_Bal_CellVoltOverFault_34 0 "Nomal" 1 "Fault" ;
VAL_ 2417487458 S2P_Bal_CellVoltLowFault_34 0 "Nomal" 1 "Fault" ;
VAL_ 2417487458 S2P_Bal_CSCPCBTempFault_34 0 "Nomal" 1 "Fault" ;
VAL_ 2417487458 S2P_Bal_CSCSourceCurrLowFault_34 0 "Nomal" 1 "Fault" ;
VAL_ 2417487458 S2P_Bal_CSCSourceCurrOvrFault_34 0 "Nomal" 1 "Fault" ;
VAL_ 2417487459 S2P_Bal_CSCNum_35 0 "No CSC" 1 "CSC 1" 2 "CSC 2" 3 "CSC 3" 4 "CSC 4" 5 "CSC 5" 6 "CSC 6" 7 "CSC 7" 8 "CSC 8" 9 "CSC 9" 10 "CSC 10" 11 "CSC 11" 12 "CSC 12" 13 "CSC 13" 14 "CSC 14" 15 "CSC 15" 16 "CSC 16" 17 "CSC 17" 18 "CSC 18" 19 "CSC 19" 20 "CSC 20" 21 "CSC 21" 22 "CSC 22" 23 "CSC 23" 24 "CSC 24" 25 "CSC 25" 26 "CSC 26" 27 "CSC 27" 28 "CSC 28" 29 "CSC 29" 30 "CSC 30" 31 "CSC 31" ;
VAL_ 2417487459 S2P_Bal_CellNum_35 1 "Cell 1" 2 "Cell 2" 3 "Cell 3" 4 "Cell 4" 5 "Cell 5" 6 "Cell 6" 7 "Cell 7" 8 "Cell 8" 9 "Cell 9" 10 "Cell 10" 11 "Cell 11" 12 "Cell 12" 13 "Cell 13" 14 "Cell 14" 15 "Cell 15" 16 "Cell 16" 63 "Null" ;
VAL_ 2417487459 S2P_Bal_Type_35 0 "Balance stop" 1 "charge Balance" 2 "discharge Balance" ;
VAL_ 2417487459 S2P_Bal_TypeLevel_35 0 "Not Balance" 1 "Low end Balance" 2 "High end Balance" 3 "Force Balance" ;
VAL_ 2417487459 S2P_Bal_SystemStatus_35 0 "Not Static" 1 "Staic Balance" 2 "Discharge false Balance" ;
VAL_ 2417487459 S2P_Bal_Strategy_35 0 "Active Balance" 1 "Passive Static" ;
VAL_ 2417487459 S2P_Bal_ForceBalMode_35 1 "Base on time " 2 "Base on Target Vol" 3 "Base on Ave Vol" ;
VAL_ 2417487459 S2P_Bal_CellTempFault_35 0 "Nomal" 1 "Fault" ;
VAL_ 2417487459 S2P_Bal_CellVoltFail_35 0 "Nomal" 1 "Fault" ;
VAL_ 2417487459 S2P_Bal_CloseBalInstruct_35 0 "Nomal" 1 "Fault" ;
VAL_ 2417487459 S2P_Bal_CCanTimeOut_35 0 "Nomal" 1 "Fault" ;
VAL_ 2417487459 S2P_Bal_CellOffLine_35 0 "Nomal" 1 "Fault" ;
VAL_ 2417487459 S2P_Bal_BalanceCircuitFault_35 0 "Nomal" 1 "Fault" ;
VAL_ 2417487459 S2P_Bal_CSCSourceVoltFault_35 0 "Nomal" 1 "Fault" ;
VAL_ 2417487459 S2P_Bal_CellVoltOverFault_35 0 "Nomal" 1 "Fault" ;
VAL_ 2417487459 S2P_Bal_CellVoltLowFault_35 0 "Nomal" 1 "Fault" ;
VAL_ 2417487459 S2P_Bal_CSCPCBTempFault_35 0 "Nomal" 1 "Fault" ;
VAL_ 2417487459 S2P_Bal_CSCSourceCurrLowFault_35 0 "Nomal" 1 "Fault" ;
VAL_ 2417487459 S2P_Bal_CSCSourceCurrOvrFault_35 0 "Nomal" 1 "Fault" ;
VAL_ 2417487460 S2P_Bal_CSCNum_36 0 "No CSC" 1 "CSC 1" 2 "CSC 2" 3 "CSC 3" 4 "CSC 4" 5 "CSC 5" 6 "CSC 6" 7 "CSC 7" 8 "CSC 8" 9 "CSC 9" 10 "CSC 10" 11 "CSC 11" 12 "CSC 12" 13 "CSC 13" 14 "CSC 14" 15 "CSC 15" 16 "CSC 16" 17 "CSC 17" 18 "CSC 18" 19 "CSC 19" 20 "CSC 20" 21 "CSC 21" 22 "CSC 22" 23 "CSC 23" 24 "CSC 24" 25 "CSC 25" 26 "CSC 26" 27 "CSC 27" 28 "CSC 28" 29 "CSC 29" 30 "CSC 30" 31 "CSC 31" ;
VAL_ 2417487460 S2P_Bal_CellNum_36 1 "Cell 1" 2 "Cell 2" 3 "Cell 3" 4 "Cell 4" 5 "Cell 5" 6 "Cell 6" 7 "Cell 7" 8 "Cell 8" 9 "Cell 9" 10 "Cell 10" 11 "Cell 11" 12 "Cell 12" 13 "Cell 13" 14 "Cell 14" 15 "Cell 15" 16 "Cell 16" 63 "Null" ;
VAL_ 2417487460 S2P_Bal_Type_36 0 "Balance stop" 1 "charge Balance" 2 "discharge Balance" ;
VAL_ 2417487460 S2P_Bal_TypeLevel_36 0 "Not Balance" 1 "Low end Balance" 2 "High end Balance" 3 "Force Balance" ;
VAL_ 2417487460 S2P_Bal_SystemStatus_36 0 "Not Static" 1 "Staic Balance" 2 "Discharge false Balance" ;
VAL_ 2417487460 S2P_Bal_Strategy_36 0 "Active Balance" 1 "Passive Static" ;
VAL_ 2417487460 S2P_Bal_ForceBalMode_36 1 "Base on time " 2 "Base on Target Vol" 3 "Base on Ave Vol" ;
VAL_ 2417487460 S2P_Bal_CellTempFault_36 0 "Nomal" 1 "Fault" ;
VAL_ 2417487460 S2P_Bal_CellVoltFail_36 0 "Nomal" 1 "Fault" ;
VAL_ 2417487460 S2P_Bal_CloseBalInstruct_36 0 "Nomal" 1 "Fault" ;
VAL_ 2417487460 S2P_Bal_CCanTimeOut_36 0 "Nomal" 1 "Fault" ;
VAL_ 2417487460 S2P_Bal_CellOffLine_36 0 "Nomal" 1 "Fault" ;
VAL_ 2417487460 S2P_Bal_BalanceCircuitFault_36 0 "Nomal" 1 "Fault" ;
VAL_ 2417487460 S2P_Bal_CSCSourceVoltFault_36 0 "Nomal" 1 "Fault" ;
VAL_ 2417487460 S2P_Bal_CellVoltOverFault_36 0 "Nomal" 1 "Fault" ;
VAL_ 2417487460 S2P_Bal_CellVoltLowFault_36 0 "Nomal" 1 "Fault" ;
VAL_ 2417487460 S2P_Bal_CSCPCBTempFault_36 0 "Nomal" 1 "Fault" ;
VAL_ 2417487460 S2P_Bal_CSCSourceCurrLowFault_36 0 "Nomal" 1 "Fault" ;
VAL_ 2417487460 S2P_Bal_CSCSourceCurrOvrFault_36 0 "Nomal" 1 "Fault" ;
VAL_ 2417487461 S2P_Bal_CSCNum_37 0 "No CSC" 1 "CSC 1" 2 "CSC 2" 3 "CSC 3" 4 "CSC 4" 5 "CSC 5" 6 "CSC 6" 7 "CSC 7" 8 "CSC 8" 9 "CSC 9" 10 "CSC 10" 11 "CSC 11" 12 "CSC 12" 13 "CSC 13" 14 "CSC 14" 15 "CSC 15" 16 "CSC 16" 17 "CSC 17" 18 "CSC 18" 19 "CSC 19" 20 "CSC 20" 21 "CSC 21" 22 "CSC 22" 23 "CSC 23" 24 "CSC 24" 25 "CSC 25" 26 "CSC 26" 27 "CSC 27" 28 "CSC 28" 29 "CSC 29" 30 "CSC 30" 31 "CSC 31" ;
VAL_ 2417487461 S2P_Bal_CellNum_37 1 "Cell 1" 2 "Cell 2" 3 "Cell 3" 4 "Cell 4" 5 "Cell 5" 6 "Cell 6" 7 "Cell 7" 8 "Cell 8" 9 "Cell 9" 10 "Cell 10" 11 "Cell 11" 12 "Cell 12" 13 "Cell 13" 14 "Cell 14" 15 "Cell 15" 16 "Cell 16" 63 "Null" ;
VAL_ 2417487461 S2P_Bal_Type_37 0 "Balance stop" 1 "charge Balance" 2 "discharge Balance" ;
VAL_ 2417487461 S2P_Bal_TypeLevel_37 0 "Not Balance" 1 "Low end Balance" 2 "High end Balance" 3 "Force Balance" ;
VAL_ 2417487461 S2P_Bal_SystemStatus_37 0 "Not Static" 1 "Staic Balance" 2 "Discharge false Balance" ;
VAL_ 2417487461 S2P_Bal_Strategy_37 0 "Active Balance" 1 "Passive Static" ;
VAL_ 2417487461 S2P_Bal_ForceBalMode_37 1 "Base on time " 2 "Base on Target Vol" 3 "Base on Ave Vol" ;
VAL_ 2417487461 S2P_Bal_CellTempFault_37 0 "Nomal" 1 "Fault" ;
VAL_ 2417487461 S2P_Bal_CellVoltFail_37 0 "Nomal" 1 "Fault" ;
VAL_ 2417487461 S2P_Bal_CloseBalInstruct_37 0 "Nomal" 1 "Fault" ;
VAL_ 2417487461 S2P_Bal_CCanTimeOut_37 0 "Nomal" 1 "Fault" ;
VAL_ 2417487461 S2P_Bal_CellOffLine_37 0 "Nomal" 1 "Fault" ;
VAL_ 2417487461 S2P_Bal_BalanceCircuitFault_37 0 "Nomal" 1 "Fault" ;
VAL_ 2417487461 S2P_Bal_CSCSourceVoltFault_37 0 "Nomal" 1 "Fault" ;
VAL_ 2417487461 S2P_Bal_CellVoltOverFault_37 0 "Nomal" 1 "Fault" ;
VAL_ 2417487461 S2P_Bal_CellVoltLowFault_37 0 "Nomal" 1 "Fault" ;
VAL_ 2417487461 S2P_Bal_CSCPCBTempFault_37 0 "Nomal" 1 "Fault" ;
VAL_ 2417487461 S2P_Bal_CSCSourceCurrLowFault_37 0 "Nomal" 1 "Fault" ;
VAL_ 2417487461 S2P_Bal_CSCSourceCurrOvrFault_37 0 "Nomal" 1 "Fault" ;
VAL_ 2417487462 S2P_Bal_CSCNum_38 0 "No CSC" 1 "CSC 1" 2 "CSC 2" 3 "CSC 3" 4 "CSC 4" 5 "CSC 5" 6 "CSC 6" 7 "CSC 7" 8 "CSC 8" 9 "CSC 9" 10 "CSC 10" 11 "CSC 11" 12 "CSC 12" 13 "CSC 13" 14 "CSC 14" 15 "CSC 15" 16 "CSC 16" 17 "CSC 17" 18 "CSC 18" 19 "CSC 19" 20 "CSC 20" 21 "CSC 21" 22 "CSC 22" 23 "CSC 23" 24 "CSC 24" 25 "CSC 25" 26 "CSC 26" 27 "CSC 27" 28 "CSC 28" 29 "CSC 29" 30 "CSC 30" 31 "CSC 31" ;
VAL_ 2417487462 S2P_Bal_CellNum_38 1 "Cell 1" 2 "Cell 2" 3 "Cell 3" 4 "Cell 4" 5 "Cell 5" 6 "Cell 6" 7 "Cell 7" 8 "Cell 8" 9 "Cell 9" 10 "Cell 10" 11 "Cell 11" 12 "Cell 12" 13 "Cell 13" 14 "Cell 14" 15 "Cell 15" 16 "Cell 16" 63 "Null" ;
VAL_ 2417487462 S2P_Bal_Type_38 0 "Balance stop" 1 "charge Balance" 2 "discharge Balance" ;
VAL_ 2417487462 S2P_Bal_TypeLevel_38 0 "Not Balance" 1 "Low end Balance" 2 "High end Balance" 3 "Force Balance" ;
VAL_ 2417487462 S2P_Bal_SystemStatus_38 0 "Not Static" 1 "Staic Balance" 2 "Discharge false Balance" ;
VAL_ 2417487462 S2P_Bal_Strategy_38 0 "Active Balance" 1 "Passive Static" ;
VAL_ 2417487462 S2P_Bal_ForceBalMode_38 1 "Base on time " 2 "Base on Target Vol" 3 "Base on Ave Vol" ;
VAL_ 2417487462 S2P_Bal_CellTempFault_38 0 "Nomal" 1 "Fault" ;
VAL_ 2417487462 S2P_Bal_CellVoltFail_38 0 "Nomal" 1 "Fault" ;
VAL_ 2417487462 S2P_Bal_CloseBalInstruct_38 0 "Nomal" 1 "Fault" ;
VAL_ 2417487462 S2P_Bal_CCanTimeOut_38 0 "Nomal" 1 "Fault" ;
VAL_ 2417487462 S2P_Bal_CellOffLine_38 0 "Nomal" 1 "Fault" ;
VAL_ 2417487462 S2P_Bal_BalanceCircuitFault_38 0 "Nomal" 1 "Fault" ;
VAL_ 2417487462 S2P_Bal_CSCSourceVoltFault_38 0 "Nomal" 1 "Fault" ;
VAL_ 2417487462 S2P_Bal_CellVoltOverFault_38 0 "Nomal" 1 "Fault" ;
VAL_ 2417487462 S2P_Bal_CellVoltLowFault_38 0 "Nomal" 1 "Fault" ;
VAL_ 2417487462 S2P_Bal_CSCPCBTempFault_38 0 "Nomal" 1 "Fault" ;
VAL_ 2417487462 S2P_Bal_CSCSourceCurrLowFault_38 0 "Nomal" 1 "Fault" ;
VAL_ 2417487462 S2P_Bal_CSCSourceCurrOvrFault_38 0 "Nomal" 1 "Fault" ;
VAL_ 2417487463 S2P_Bal_CSCNum_39 0 "No CSC" 1 "CSC 1" 2 "CSC 2" 3 "CSC 3" 4 "CSC 4" 5 "CSC 5" 6 "CSC 6" 7 "CSC 7" 8 "CSC 8" 9 "CSC 9" 10 "CSC 10" 11 "CSC 11" 12 "CSC 12" 13 "CSC 13" 14 "CSC 14" 15 "CSC 15" 16 "CSC 16" 17 "CSC 17" 18 "CSC 18" 19 "CSC 19" 20 "CSC 20" 21 "CSC 21" 22 "CSC 22" 23 "CSC 23" 24 "CSC 24" 25 "CSC 25" 26 "CSC 26" 27 "CSC 27" 28 "CSC 28" 29 "CSC 29" 30 "CSC 30" 31 "CSC 31" ;
VAL_ 2417487463 S2P_Bal_CellNum_39 1 "Cell 1" 2 "Cell 2" 3 "Cell 3" 4 "Cell 4" 5 "Cell 5" 6 "Cell 6" 7 "Cell 7" 8 "Cell 8" 9 "Cell 9" 10 "Cell 10" 11 "Cell 11" 12 "Cell 12" 13 "Cell 13" 14 "Cell 14" 15 "Cell 15" 16 "Cell 16" 63 "Null" ;
VAL_ 2417487463 S2P_Bal_Type_39 0 "Balance stop" 1 "charge Balance" 2 "discharge Balance" ;
VAL_ 2417487463 S2P_Bal_TypeLevel_39 0 "Not Balance" 1 "Low end Balance" 2 "High end Balance" 3 "Force Balance" ;
VAL_ 2417487463 S2P_Bal_SystemStatus_39 0 "Not Static" 1 "Staic Balance" 2 "Discharge false Balance" ;
VAL_ 2417487463 S2P_Bal_Strategy_39 0 "Active Balance" 1 "Passive Static" ;
VAL_ 2417487463 S2P_Bal_ForceBalMode_39 1 "Base on time " 2 "Base on Target Vol" 3 "Base on Ave Vol" ;
VAL_ 2417487463 S2P_Bal_CellTempFault_39 0 "Nomal" 1 "Fault" ;
VAL_ 2417487463 S2P_Bal_CellVoltFail_39 0 "Nomal" 1 "Fault" ;
VAL_ 2417487463 S2P_Bal_CloseBalInstruct_39 0 "Nomal" 1 "Fault" ;
VAL_ 2417487463 S2P_Bal_CCanTimeOut_39 0 "Nomal" 1 "Fault" ;
VAL_ 2417487463 S2P_Bal_CellOffLine_39 0 "Nomal" 1 "Fault" ;
VAL_ 2417487463 S2P_Bal_BalanceCircuitFault_39 0 "Nomal" 1 "Fault" ;
VAL_ 2417487463 S2P_Bal_CSCSourceVoltFault_39 0 "Nomal" 1 "Fault" ;
VAL_ 2417487463 S2P_Bal_CellVoltOverFault_39 0 "Nomal" 1 "Fault" ;
VAL_ 2417487463 S2P_Bal_CellVoltLowFault_39 0 "Nomal" 1 "Fault" ;
VAL_ 2417487463 S2P_Bal_CSCPCBTempFault_39 0 "Nomal" 1 "Fault" ;
VAL_ 2417487463 S2P_Bal_CSCSourceCurrLowFault_39 0 "Nomal" 1 "Fault" ;
VAL_ 2417487463 S2P_Bal_CSCSourceCurrOvrFault_39 0 "Nomal" 1 "Fault" ;
VAL_ 2417487464 S2P_Bal_CSCNum_40 0 "No CSC" 1 "CSC 1" 2 "CSC 2" 3 "CSC 3" 4 "CSC 4" 5 "CSC 5" 6 "CSC 6" 7 "CSC 7" 8 "CSC 8" 9 "CSC 9" 10 "CSC 10" 11 "CSC 11" 12 "CSC 12" 13 "CSC 13" 14 "CSC 14" 15 "CSC 15" 16 "CSC 16" 17 "CSC 17" 18 "CSC 18" 19 "CSC 19" 20 "CSC 20" 21 "CSC 21" 22 "CSC 22" 23 "CSC 23" 24 "CSC 24" 25 "CSC 25" 26 "CSC 26" 27 "CSC 27" 28 "CSC 28" 29 "CSC 29" 30 "CSC 30" 31 "CSC 31" ;
VAL_ 2417487464 S2P_Bal_CellNum_40 1 "Cell 1" 2 "Cell 2" 3 "Cell 3" 4 "Cell 4" 5 "Cell 5" 6 "Cell 6" 7 "Cell 7" 8 "Cell 8" 9 "Cell 9" 10 "Cell 10" 11 "Cell 11" 12 "Cell 12" 13 "Cell 13" 14 "Cell 14" 15 "Cell 15" 16 "Cell 16" 63 "Null" ;
VAL_ 2417487464 S2P_Bal_Type_40 0 "Balance stop" 1 "charge Balance" 2 "discharge Balance" ;
VAL_ 2417487464 S2P_Bal_TypeLevel_40 0 "Not Balance" 1 "Low end Balance" 2 "High end Balance" 3 "Force Balance" ;
VAL_ 2417487464 S2P_Bal_SystemStatus_40 0 "Not Static" 1 "Staic Balance" 2 "Discharge false Balance" ;
VAL_ 2417487464 S2P_Bal_Strategy_40 0 "Active Balance" 1 "Passive Static" ;
VAL_ 2417487464 S2P_Bal_ForceBalMode_40 1 "Base on time " 2 "Base on Target Vol" 3 "Base on Ave Vol" ;
VAL_ 2417487464 S2P_Bal_CellTempFault_40 0 "Nomal" 1 "Fault" ;
VAL_ 2417487464 S2P_Bal_CellVoltFail_40 0 "Nomal" 1 "Fault" ;
VAL_ 2417487464 S2P_Bal_CloseBalInstruct_40 0 "Nomal" 1 "Fault" ;
VAL_ 2417487464 S2P_Bal_CCanTimeOut_40 0 "Nomal" 1 "Fault" ;
VAL_ 2417487464 S2P_Bal_CellOffLine_40 0 "Nomal" 1 "Fault" ;
VAL_ 2417487464 S2P_Bal_BalanceCircuitFault_40 0 "Nomal" 1 "Fault" ;
VAL_ 2417487464 S2P_Bal_CSCSourceVoltFault_40 0 "Nomal" 1 "Fault" ;
VAL_ 2417487464 S2P_Bal_CellVoltOverFault_40 0 "Nomal" 1 "Fault" ;
VAL_ 2417487464 S2P_Bal_CellVoltLowFault_40 0 "Nomal" 1 "Fault" ;
VAL_ 2417487464 S2P_Bal_CSCPCBTempFault_40 0 "Nomal" 1 "Fault" ;
VAL_ 2417487464 S2P_Bal_CSCSourceCurrLowFault_40 0 "Nomal" 1 "Fault" ;
VAL_ 2417487464 S2P_Bal_CSCSourceCurrOvrFault_40 0 "Nomal" 1 "Fault" ;
VAL_ 2417487465 S2P_Bal_CSCNum_41 0 "No CSC" 1 "CSC 1" 2 "CSC 2" 3 "CSC 3" 4 "CSC 4" 5 "CSC 5" 6 "CSC 6" 7 "CSC 7" 8 "CSC 8" 9 "CSC 9" 10 "CSC 10" 11 "CSC 11" 12 "CSC 12" 13 "CSC 13" 14 "CSC 14" 15 "CSC 15" 16 "CSC 16" 17 "CSC 17" 18 "CSC 18" 19 "CSC 19" 20 "CSC 20" 21 "CSC 21" 22 "CSC 22" 23 "CSC 23" 24 "CSC 24" 25 "CSC 25" 26 "CSC 26" 27 "CSC 27" 28 "CSC 28" 29 "CSC 29" 30 "CSC 30" 31 "CSC 31" ;
VAL_ 2417487465 S2P_Bal_CellNum_41 1 "Cell 1" 2 "Cell 2" 3 "Cell 3" 4 "Cell 4" 5 "Cell 5" 6 "Cell 6" 7 "Cell 7" 8 "Cell 8" 9 "Cell 9" 10 "Cell 10" 11 "Cell 11" 12 "Cell 12" 13 "Cell 13" 14 "Cell 14" 15 "Cell 15" 16 "Cell 16" 63 "Null" ;
VAL_ 2417487465 S2P_Bal_Type_41 0 "Balance stop" 1 "charge Balance" 2 "discharge Balance" ;
VAL_ 2417487465 S2P_Bal_TypeLevel_41 0 "Not Balance" 1 "Low end Balance" 2 "High end Balance" 3 "Force Balance" ;
VAL_ 2417487465 S2P_Bal_SystemStatus_41 0 "Not Static" 1 "Staic Balance" 2 "Discharge false Balance" ;
VAL_ 2417487465 S2P_Bal_Strategy_41 0 "Active Balance" 1 "Passive Static" ;
VAL_ 2417487465 S2P_Bal_ForceBalMode_41 1 "Base on time " 2 "Base on Target Vol" 3 "Base on Ave Vol" ;
VAL_ 2417487465 S2P_Bal_CellTempFault_41 0 "Nomal" 1 "Fault" ;
VAL_ 2417487465 S2P_Bal_CellVoltFail_41 0 "Nomal" 1 "Fault" ;
VAL_ 2417487465 S2P_Bal_CloseBalInstruct_41 0 "Nomal" 1 "Fault" ;
VAL_ 2417487465 S2P_Bal_CCanTimeOut_41 0 "Nomal" 1 "Fault" ;
VAL_ 2417487465 S2P_Bal_CellOffLine_41 0 "Nomal" 1 "Fault" ;
VAL_ 2417487465 S2P_Bal_BalanceCircuitFault_41 0 "Nomal" 1 "Fault" ;
VAL_ 2417487465 S2P_Bal_CSCSourceVoltFault_41 0 "Nomal" 1 "Fault" ;
VAL_ 2417487465 S2P_Bal_CellVoltOverFault_41 0 "Nomal" 1 "Fault" ;
VAL_ 2417487465 S2P_Bal_CellVoltLowFault_41 0 "Nomal" 1 "Fault" ;
VAL_ 2417487465 S2P_Bal_CSCPCBTempFault_41 0 "Nomal" 1 "Fault" ;
VAL_ 2417487465 S2P_Bal_CSCSourceCurrLowFault_41 0 "Nomal" 1 "Fault" ;
VAL_ 2417487465 S2P_Bal_CSCSourceCurrOvrFault_41 0 "Nomal" 1 "Fault" ;
VAL_ 2417487466 S2P_Bal_CSCNum_42 0 "No CSC" 1 "CSC 1" 2 "CSC 2" 3 "CSC 3" 4 "CSC 4" 5 "CSC 5" 6 "CSC 6" 7 "CSC 7" 8 "CSC 8" 9 "CSC 9" 10 "CSC 10" 11 "CSC 11" 12 "CSC 12" 13 "CSC 13" 14 "CSC 14" 15 "CSC 15" 16 "CSC 16" 17 "CSC 17" 18 "CSC 18" 19 "CSC 19" 20 "CSC 20" 21 "CSC 21" 22 "CSC 22" 23 "CSC 23" 24 "CSC 24" 25 "CSC 25" 26 "CSC 26" 27 "CSC 27" 28 "CSC 28" 29 "CSC 29" 30 "CSC 30" 31 "CSC 31" ;
VAL_ 2417487466 S2P_Bal_CellNum_42 1 "Cell 1" 2 "Cell 2" 3 "Cell 3" 4 "Cell 4" 5 "Cell 5" 6 "Cell 6" 7 "Cell 7" 8 "Cell 8" 9 "Cell 9" 10 "Cell 10" 11 "Cell 11" 12 "Cell 12" 13 "Cell 13" 14 "Cell 14" 15 "Cell 15" 16 "Cell 16" 63 "Null" ;
VAL_ 2417487466 S2P_Bal_Type_42 0 "Balance stop" 1 "charge Balance" 2 "discharge Balance" ;
VAL_ 2417487466 S2P_Bal_TypeLevel_42 0 "Not Balance" 1 "Low end Balance" 2 "High end Balance" 3 "Force Balance" ;
VAL_ 2417487466 S2P_Bal_SystemStatus_42 0 "Not Static" 1 "Staic Balance" 2 "Discharge false Balance" ;
VAL_ 2417487466 S2P_Bal_Strategy_42 0 "Active Balance" 1 "Passive Static" ;
VAL_ 2417487466 S2P_Bal_ForceBalMode_42 1 "Base on time " 2 "Base on Target Vol" 3 "Base on Ave Vol" ;
VAL_ 2417487466 S2P_Bal_CellTempFault_42 0 "Nomal" 1 "Fault" ;
VAL_ 2417487466 S2P_Bal_CellVoltFail_42 0 "Nomal" 1 "Fault" ;
VAL_ 2417487466 S2P_Bal_CloseBalInstruct_42 0 "Nomal" 1 "Fault" ;
VAL_ 2417487466 S2P_Bal_CCanTimeOut_42 0 "Nomal" 1 "Fault" ;
VAL_ 2417487466 S2P_Bal_CellOffLine_42 0 "Nomal" 1 "Fault" ;
VAL_ 2417487466 S2P_Bal_BalanceCircuitFault_42 0 "Nomal" 1 "Fault" ;
VAL_ 2417487466 S2P_Bal_CSCSourceVoltFault_42 0 "Nomal" 1 "Fault" ;
VAL_ 2417487466 S2P_Bal_CellVoltOverFault_42 0 "Nomal" 1 "Fault" ;
VAL_ 2417487466 S2P_Bal_CellVoltLowFault_42 0 "Nomal" 1 "Fault" ;
VAL_ 2417487466 S2P_Bal_CSCPCBTempFault_42 0 "Nomal" 1 "Fault" ;
VAL_ 2417487466 S2P_Bal_CSCSourceCurrLowFault_42 0 "Nomal" 1 "Fault" ;
VAL_ 2417487466 S2P_Bal_CSCSourceCurrOvrFault_42 0 "Nomal" 1 "Fault" ;
VAL_ 2417487467 S2P_Bal_CSCNum_43 0 "No CSC" 1 "CSC 1" 2 "CSC 2" 3 "CSC 3" 4 "CSC 4" 5 "CSC 5" 6 "CSC 6" 7 "CSC 7" 8 "CSC 8" 9 "CSC 9" 10 "CSC 10" 11 "CSC 11" 12 "CSC 12" 13 "CSC 13" 14 "CSC 14" 15 "CSC 15" 16 "CSC 16" 17 "CSC 17" 18 "CSC 18" 19 "CSC 19" 20 "CSC 20" 21 "CSC 21" 22 "CSC 22" 23 "CSC 23" 24 "CSC 24" 25 "CSC 25" 26 "CSC 26" 27 "CSC 27" 28 "CSC 28" 29 "CSC 29" 30 "CSC 30" 31 "CSC 31" ;
VAL_ 2417487467 S2P_Bal_CellNum_43 1 "Cell 1" 2 "Cell 2" 3 "Cell 3" 4 "Cell 4" 5 "Cell 5" 6 "Cell 6" 7 "Cell 7" 8 "Cell 8" 9 "Cell 9" 10 "Cell 10" 11 "Cell 11" 12 "Cell 12" 13 "Cell 13" 14 "Cell 14" 15 "Cell 15" 16 "Cell 16" 63 "Null" ;
VAL_ 2417487467 S2P_Bal_Type_43 0 "Balance stop" 1 "charge Balance" 2 "discharge Balance" ;
VAL_ 2417487467 S2P_Bal_TypeLevel_43 0 "Not Balance" 1 "Low end Balance" 2 "High end Balance" 3 "Force Balance" ;
VAL_ 2417487467 S2P_Bal_SystemStatus_43 0 "Not Static" 1 "Staic Balance" 2 "Discharge false Balance" ;
VAL_ 2417487467 S2P_Bal_Strategy_43 0 "Active Balance" 1 "Passive Static" ;
VAL_ 2417487467 S2P_Bal_ForceBalMode_43 1 "Base on time " 2 "Base on Target Vol" 3 "Base on Ave Vol" ;
VAL_ 2417487467 S2P_Bal_CellTempFault_43 0 "Nomal" 1 "Fault" ;
VAL_ 2417487467 S2P_Bal_CellVoltFail_43 0 "Nomal" 1 "Fault" ;
VAL_ 2417487467 S2P_Bal_CloseBalInstruct_43 0 "Nomal" 1 "Fault" ;
VAL_ 2417487467 S2P_Bal_CCanTimeOut_43 0 "Nomal" 1 "Fault" ;
VAL_ 2417487467 S2P_Bal_CellOffLine_43 0 "Nomal" 1 "Fault" ;
VAL_ 2417487467 S2P_Bal_BalanceCircuitFault_43 0 "Nomal" 1 "Fault" ;
VAL_ 2417487467 S2P_Bal_CSCSourceVoltFault_43 0 "Nomal" 1 "Fault" ;
VAL_ 2417487467 S2P_Bal_CellVoltOverFault_43 0 "Nomal" 1 "Fault" ;
VAL_ 2417487467 S2P_Bal_CellVoltLowFault_43 0 "Nomal" 1 "Fault" ;
VAL_ 2417487467 S2P_Bal_CSCPCBTempFault_43 0 "Nomal" 1 "Fault" ;
VAL_ 2417487467 S2P_Bal_CSCSourceCurrLowFault_43 0 "Nomal" 1 "Fault" ;
VAL_ 2417487467 S2P_Bal_CSCSourceCurrOvrFault_43 0 "Nomal" 1 "Fault" ;
VAL_ 2417487468 S2P_Bal_CSCNum_44 0 "No CSC" 1 "CSC 1" 2 "CSC 2" 3 "CSC 3" 4 "CSC 4" 5 "CSC 5" 6 "CSC 6" 7 "CSC 7" 8 "CSC 8" 9 "CSC 9" 10 "CSC 10" 11 "CSC 11" 12 "CSC 12" 13 "CSC 13" 14 "CSC 14" 15 "CSC 15" 16 "CSC 16" 17 "CSC 17" 18 "CSC 18" 19 "CSC 19" 20 "CSC 20" 21 "CSC 21" 22 "CSC 22" 23 "CSC 23" 24 "CSC 24" 25 "CSC 25" 26 "CSC 26" 27 "CSC 27" 28 "CSC 28" 29 "CSC 29" 30 "CSC 30" 31 "CSC 31" ;
VAL_ 2417487468 S2P_Bal_CellNum_44 1 "Cell 1" 2 "Cell 2" 3 "Cell 3" 4 "Cell 4" 5 "Cell 5" 6 "Cell 6" 7 "Cell 7" 8 "Cell 8" 9 "Cell 9" 10 "Cell 10" 11 "Cell 11" 12 "Cell 12" 13 "Cell 13" 14 "Cell 14" 15 "Cell 15" 16 "Cell 16" 63 "Null" ;
VAL_ 2417487468 S2P_Bal_Type_44 0 "Balance stop" 1 "charge Balance" 2 "discharge Balance" ;
VAL_ 2417487468 S2P_Bal_TypeLevel_44 0 "Not Balance" 1 "Low end Balance" 2 "High end Balance" 3 "Force Balance" ;
VAL_ 2417487468 S2P_Bal_SystemStatus_44 0 "Not Static" 1 "Staic Balance" 2 "Discharge false Balance" ;
VAL_ 2417487468 S2P_Bal_Strategy_44 0 "Active Balance" 1 "Passive Static" ;
VAL_ 2417487468 S2P_Bal_ForceBalMode_44 1 "Base on time " 2 "Base on Target Vol" 3 "Base on Ave Vol" ;
VAL_ 2417487468 S2P_Bal_CellTempFault_44 0 "Nomal" 1 "Fault" ;
VAL_ 2417487468 S2P_Bal_CellVoltFail_44 0 "Nomal" 1 "Fault" ;
VAL_ 2417487468 S2P_Bal_CloseBalInstruct_44 0 "Nomal" 1 "Fault" ;
VAL_ 2417487468 S2P_Bal_CCanTimeOut_44 0 "Nomal" 1 "Fault" ;
VAL_ 2417487468 S2P_Bal_CellOffLine_44 0 "Nomal" 1 "Fault" ;
VAL_ 2417487468 S2P_Bal_BalanceCircuitFault_44 0 "Nomal" 1 "Fault" ;
VAL_ 2417487468 S2P_Bal_CSCSourceVoltFault_44 0 "Nomal" 1 "Fault" ;
VAL_ 2417487468 S2P_Bal_CellVoltOverFault_44 0 "Nomal" 1 "Fault" ;
VAL_ 2417487468 S2P_Bal_CellVoltLowFault_44 0 "Nomal" 1 "Fault" ;
VAL_ 2417487468 S2P_Bal_CSCPCBTempFault_44 0 "Nomal" 1 "Fault" ;
VAL_ 2417487468 S2P_Bal_CSCSourceCurrLowFault_44 0 "Nomal" 1 "Fault" ;
VAL_ 2417487468 S2P_Bal_CSCSourceCurrOvrFault_44 0 "Nomal" 1 "Fault" ;
VAL_ 2417487469 S2P_Bal_CSCNum_45 0 "No CSC" 1 "CSC 1" 2 "CSC 2" 3 "CSC 3" 4 "CSC 4" 5 "CSC 5" 6 "CSC 6" 7 "CSC 7" 8 "CSC 8" 9 "CSC 9" 10 "CSC 10" 11 "CSC 11" 12 "CSC 12" 13 "CSC 13" 14 "CSC 14" 15 "CSC 15" 16 "CSC 16" 17 "CSC 17" 18 "CSC 18" 19 "CSC 19" 20 "CSC 20" 21 "CSC 21" 22 "CSC 22" 23 "CSC 23" 24 "CSC 24" 25 "CSC 25" 26 "CSC 26" 27 "CSC 27" 28 "CSC 28" 29 "CSC 29" 30 "CSC 30" 31 "CSC 31" ;
VAL_ 2417487469 S2P_Bal_CellNum_45 1 "Cell 1" 2 "Cell 2" 3 "Cell 3" 4 "Cell 4" 5 "Cell 5" 6 "Cell 6" 7 "Cell 7" 8 "Cell 8" 9 "Cell 9" 10 "Cell 10" 11 "Cell 11" 12 "Cell 12" 13 "Cell 13" 14 "Cell 14" 15 "Cell 15" 16 "Cell 16" 63 "Null" ;
VAL_ 2417487469 S2P_Bal_Type_45 0 "Balance stop" 1 "charge Balance" 2 "discharge Balance" ;
VAL_ 2417487469 S2P_Bal_TypeLevel_45 0 "Not Balance" 1 "Low end Balance" 2 "High end Balance" 3 "Force Balance" ;
VAL_ 2417487469 S2P_Bal_SystemStatus_45 0 "Not Static" 1 "Staic Balance" 2 "Discharge false Balance" ;
VAL_ 2417487469 S2P_Bal_Strategy_45 0 "Active Balance" 1 "Passive Static" ;
VAL_ 2417487469 S2P_Bal_ForceBalMode_45 1 "Base on time " 2 "Base on Target Vol" 3 "Base on Ave Vol" ;
VAL_ 2417487469 S2P_Bal_CellTempFault_45 0 "Nomal" 1 "Fault" ;
VAL_ 2417487469 S2P_Bal_CellVoltFail_45 0 "Nomal" 1 "Fault" ;
VAL_ 2417487469 S2P_Bal_CloseBalInstruct_45 0 "Nomal" 1 "Fault" ;
VAL_ 2417487469 S2P_Bal_CCanTimeOut_45 0 "Nomal" 1 "Fault" ;
VAL_ 2417487469 S2P_Bal_CellOffLine_45 0 "Nomal" 1 "Fault" ;
VAL_ 2417487469 S2P_Bal_BalanceCircuitFault_45 0 "Nomal" 1 "Fault" ;
VAL_ 2417487469 S2P_Bal_CSCSourceVoltFault_45 0 "Nomal" 1 "Fault" ;
VAL_ 2417487469 S2P_Bal_CellVoltOverFault_45 0 "Nomal" 1 "Fault" ;
VAL_ 2417487469 S2P_Bal_CellVoltLowFault_45 0 "Nomal" 1 "Fault" ;
VAL_ 2417487469 S2P_Bal_CSCPCBTempFault_45 0 "Nomal" 1 "Fault" ;
VAL_ 2417487469 S2P_Bal_CSCSourceCurrLowFault_45 0 "Nomal" 1 "Fault" ;
VAL_ 2417487469 S2P_Bal_CSCSourceCurrOvrFault_45 0 "Nomal" 1 "Fault" ;
VAL_ 2417487470 S2P_Bal_CSCNum_46 0 "No CSC" 1 "CSC 1" 2 "CSC 2" 3 "CSC 3" 4 "CSC 4" 5 "CSC 5" 6 "CSC 6" 7 "CSC 7" 8 "CSC 8" 9 "CSC 9" 10 "CSC 10" 11 "CSC 11" 12 "CSC 12" 13 "CSC 13" 14 "CSC 14" 15 "CSC 15" 16 "CSC 16" 17 "CSC 17" 18 "CSC 18" 19 "CSC 19" 20 "CSC 20" 21 "CSC 21" 22 "CSC 22" 23 "CSC 23" 24 "CSC 24" 25 "CSC 25" 26 "CSC 26" 27 "CSC 27" 28 "CSC 28" 29 "CSC 29" 30 "CSC 30" 31 "CSC 31" ;
VAL_ 2417487470 S2P_Bal_CellNum_46 1 "Cell 1" 2 "Cell 2" 3 "Cell 3" 4 "Cell 4" 5 "Cell 5" 6 "Cell 6" 7 "Cell 7" 8 "Cell 8" 9 "Cell 9" 10 "Cell 10" 11 "Cell 11" 12 "Cell 12" 13 "Cell 13" 14 "Cell 14" 15 "Cell 15" 16 "Cell 16" 63 "Null" ;
VAL_ 2417487470 S2P_Bal_Type_46 0 "Balance stop" 1 "charge Balance" 2 "discharge Balance" ;
VAL_ 2417487470 S2P_Bal_TypeLevel_46 0 "Not Balance" 1 "Low end Balance" 2 "High end Balance" 3 "Force Balance" ;
VAL_ 2417487470 S2P_Bal_SystemStatus_46 0 "Not Static" 1 "Staic Balance" 2 "Discharge false Balance" ;
VAL_ 2417487470 S2P_Bal_Strategy_46 0 "Active Balance" 1 "Passive Static" ;
VAL_ 2417487470 S2P_Bal_ForceBalMode_46 1 "Base on time " 2 "Base on Target Vol" 3 "Base on Ave Vol" ;
VAL_ 2417487470 S2P_Bal_CellTempFault_46 0 "Nomal" 1 "Fault" ;
VAL_ 2417487470 S2P_Bal_CellVoltFail_46 0 "Nomal" 1 "Fault" ;
VAL_ 2417487470 S2P_Bal_CloseBalInstruct_46 0 "Nomal" 1 "Fault" ;
VAL_ 2417487470 S2P_Bal_CCanTimeOut_46 0 "Nomal" 1 "Fault" ;
VAL_ 2417487470 S2P_Bal_CellOffLine_46 0 "Nomal" 1 "Fault" ;
VAL_ 2417487470 S2P_Bal_BalanceCircuitFault_46 0 "Nomal" 1 "Fault" ;
VAL_ 2417487470 S2P_Bal_CSCSourceVoltFault_46 0 "Nomal" 1 "Fault" ;
VAL_ 2417487470 S2P_Bal_CellVoltOverFault_46 0 "Nomal" 1 "Fault" ;
VAL_ 2417487470 S2P_Bal_CellVoltLowFault_46 0 "Nomal" 1 "Fault" ;
VAL_ 2417487470 S2P_Bal_CSCPCBTempFault_46 0 "Nomal" 1 "Fault" ;
VAL_ 2417487470 S2P_Bal_CSCSourceCurrLowFault_46 0 "Nomal" 1 "Fault" ;
VAL_ 2417487470 S2P_Bal_CSCSourceCurrOvrFault_46 0 "Nomal" 1 "Fault" ;
VAL_ 2417487471 S2P_Bal_CSCNum_47 0 "No CSC" 1 "CSC 1" 2 "CSC 2" 3 "CSC 3" 4 "CSC 4" 5 "CSC 5" 6 "CSC 6" 7 "CSC 7" 8 "CSC 8" 9 "CSC 9" 10 "CSC 10" 11 "CSC 11" 12 "CSC 12" 13 "CSC 13" 14 "CSC 14" 15 "CSC 15" 16 "CSC 16" 17 "CSC 17" 18 "CSC 18" 19 "CSC 19" 20 "CSC 20" 21 "CSC 21" 22 "CSC 22" 23 "CSC 23" 24 "CSC 24" 25 "CSC 25" 26 "CSC 26" 27 "CSC 27" 28 "CSC 28" 29 "CSC 29" 30 "CSC 30" 31 "CSC 31" ;
VAL_ 2417487471 S2P_Bal_CellNum_47 1 "Cell 1" 2 "Cell 2" 3 "Cell 3" 4 "Cell 4" 5 "Cell 5" 6 "Cell 6" 7 "Cell 7" 8 "Cell 8" 9 "Cell 9" 10 "Cell 10" 11 "Cell 11" 12 "Cell 12" 13 "Cell 13" 14 "Cell 14" 15 "Cell 15" 16 "Cell 16" 63 "Null" ;
VAL_ 2417487471 S2P_Bal_Type_47 0 "Balance stop" 1 "charge Balance" 2 "discharge Balance" ;
VAL_ 2417487471 S2P_Bal_TypeLevel_47 0 "Not Balance" 1 "Low end Balance" 2 "High end Balance" 3 "Force Balance" ;
VAL_ 2417487471 S2P_Bal_SystemStatus_47 0 "Not Static" 1 "Staic Balance" 2 "Discharge false Balance" ;
VAL_ 2417487471 S2P_Bal_Strategy_47 0 "Active Balance" 1 "Passive Static" ;
VAL_ 2417487471 S2P_Bal_ForceBalMode_47 1 "Base on time " 2 "Base on Target Vol" 3 "Base on Ave Vol" ;
VAL_ 2417487471 S2P_Bal_CellTempFault_47 0 "Nomal" 1 "Fault" ;
VAL_ 2417487471 S2P_Bal_CellVoltFail_47 0 "Nomal" 1 "Fault" ;
VAL_ 2417487471 S2P_Bal_CloseBalInstruct_47 0 "Nomal" 1 "Fault" ;
VAL_ 2417487471 S2P_Bal_CCanTimeOut_47 0 "Nomal" 1 "Fault" ;
VAL_ 2417487471 S2P_Bal_CellOffLine_47 0 "Nomal" 1 "Fault" ;
VAL_ 2417487471 S2P_Bal_BalanceCircuitFault_47 0 "Nomal" 1 "Fault" ;
VAL_ 2417487471 S2P_Bal_CSCSourceVoltFault_47 0 "Nomal" 1 "Fault" ;
VAL_ 2417487471 S2P_Bal_CellVoltOverFault_47 0 "Nomal" 1 "Fault" ;
VAL_ 2417487471 S2P_Bal_CellVoltLowFault_47 0 "Nomal" 1 "Fault" ;
VAL_ 2417487471 S2P_Bal_CSCPCBTempFault_47 0 "Nomal" 1 "Fault" ;
VAL_ 2417487471 S2P_Bal_CSCSourceCurrLowFault_47 0 "Nomal" 1 "Fault" ;
VAL_ 2417487471 S2P_Bal_CSCSourceCurrOvrFault_47 0 "Nomal" 1 "Fault" ;
VAL_ 2417487472 S2P_Bal_CSCNum_48 0 "No CSC" 1 "CSC 1" 2 "CSC 2" 3 "CSC 3" 4 "CSC 4" 5 "CSC 5" 6 "CSC 6" 7 "CSC 7" 8 "CSC 8" 9 "CSC 9" 10 "CSC 10" 11 "CSC 11" 12 "CSC 12" 13 "CSC 13" 14 "CSC 14" 15 "CSC 15" 16 "CSC 16" 17 "CSC 17" 18 "CSC 18" 19 "CSC 19" 20 "CSC 20" 21 "CSC 21" 22 "CSC 22" 23 "CSC 23" 24 "CSC 24" 25 "CSC 25" 26 "CSC 26" 27 "CSC 27" 28 "CSC 28" 29 "CSC 29" 30 "CSC 30" 31 "CSC 31" ;
VAL_ 2417487472 S2P_Bal_CellNum_48 1 "Cell 1" 2 "Cell 2" 3 "Cell 3" 4 "Cell 4" 5 "Cell 5" 6 "Cell 6" 7 "Cell 7" 8 "Cell 8" 9 "Cell 9" 10 "Cell 10" 11 "Cell 11" 12 "Cell 12" 13 "Cell 13" 14 "Cell 14" 15 "Cell 15" 16 "Cell 16" 63 "Null" ;
VAL_ 2417487472 S2P_Bal_Type_48 0 "Balance stop" 1 "charge Balance" 2 "discharge Balance" ;
VAL_ 2417487472 S2P_Bal_TypeLevel_48 0 "Not Balance" 1 "Low end Balance" 2 "High end Balance" 3 "Force Balance" ;
VAL_ 2417487472 S2P_Bal_SystemStatus_48 0 "Not Static" 1 "Staic Balance" 2 "Discharge false Balance" ;
VAL_ 2417487472 S2P_Bal_Strategy_48 0 "Active Balance" 1 "Passive Static" ;
VAL_ 2417487472 S2P_Bal_ForceBalMode_48 1 "Base on time " 2 "Base on Target Vol" 3 "Base on Ave Vol" ;
VAL_ 2417487472 S2P_Bal_CellTempFault_48 0 "Nomal" 1 "Fault" ;
VAL_ 2417487472 S2P_Bal_CellVoltFail_48 0 "Nomal" 1 "Fault" ;
VAL_ 2417487472 S2P_Bal_CloseBalInstruct_48 0 "Nomal" 1 "Fault" ;
VAL_ 2417487472 S2P_Bal_CCanTimeOut_48 0 "Nomal" 1 "Fault" ;
VAL_ 2417487472 S2P_Bal_CellOffLine_48 0 "Nomal" 1 "Fault" ;
VAL_ 2417487472 S2P_Bal_BalanceCircuitFault_48 0 "Nomal" 1 "Fault" ;
VAL_ 2417487472 S2P_Bal_CSCSourceVoltFault_48 0 "Nomal" 1 "Fault" ;
VAL_ 2417487472 S2P_Bal_CellVoltOverFault_48 0 "Nomal" 1 "Fault" ;
VAL_ 2417487472 S2P_Bal_CellVoltLowFault_48 0 "Nomal" 1 "Fault" ;
VAL_ 2417487472 S2P_Bal_CSCPCBTempFault_48 0 "Nomal" 1 "Fault" ;
VAL_ 2417487472 S2P_Bal_CSCSourceCurrLowFault_48 0 "Nomal" 1 "Fault" ;
VAL_ 2417487472 S2P_Bal_CSCSourceCurrOvrFault_48 0 "Nomal" 1 "Fault" ;
VAL_ 2417487473 S2P_Bal_CSCNum_49 0 "No CSC" 1 "CSC 1" 2 "CSC 2" 3 "CSC 3" 4 "CSC 4" 5 "CSC 5" 6 "CSC 6" 7 "CSC 7" 8 "CSC 8" 9 "CSC 9" 10 "CSC 10" 11 "CSC 11" 12 "CSC 12" 13 "CSC 13" 14 "CSC 14" 15 "CSC 15" 16 "CSC 16" 17 "CSC 17" 18 "CSC 18" 19 "CSC 19" 20 "CSC 20" 21 "CSC 21" 22 "CSC 22" 23 "CSC 23" 24 "CSC 24" 25 "CSC 25" 26 "CSC 26" 27 "CSC 27" 28 "CSC 28" 29 "CSC 29" 30 "CSC 30" 31 "CSC 31" ;
VAL_ 2417487473 S2P_Bal_CellNum_49 1 "Cell 1" 2 "Cell 2" 3 "Cell 3" 4 "Cell 4" 5 "Cell 5" 6 "Cell 6" 7 "Cell 7" 8 "Cell 8" 9 "Cell 9" 10 "Cell 10" 11 "Cell 11" 12 "Cell 12" 13 "Cell 13" 14 "Cell 14" 15 "Cell 15" 16 "Cell 16" 63 "Null" ;
VAL_ 2417487473 S2P_Bal_Type_49 0 "Balance stop" 1 "charge Balance" 2 "discharge Balance" ;
VAL_ 2417487473 S2P_Bal_TypeLevel_49 0 "Not Balance" 1 "Low end Balance" 2 "High end Balance" 3 "Force Balance" ;
VAL_ 2417487473 S2P_Bal_SystemStatus_49 0 "Not Static" 1 "Staic Balance" 2 "Discharge false Balance" ;
VAL_ 2417487473 S2P_Bal_Strategy_49 0 "Active Balance" 1 "Passive Static" ;
VAL_ 2417487473 S2P_Bal_ForceBalMode_49 1 "Base on time " 2 "Base on Target Vol" 3 "Base on Ave Vol" ;
VAL_ 2417487473 S2P_Bal_CellTempFault_49 0 "Nomal" 1 "Fault" ;
VAL_ 2417487473 S2P_Bal_CellVoltFail_49 0 "Nomal" 1 "Fault" ;
VAL_ 2417487473 S2P_Bal_CloseBalInstruct_49 0 "Nomal" 1 "Fault" ;
VAL_ 2417487473 S2P_Bal_CCanTimeOut_49 0 "Nomal" 1 "Fault" ;
VAL_ 2417487473 S2P_Bal_CellOffLine_49 0 "Nomal" 1 "Fault" ;
VAL_ 2417487473 S2P_Bal_BalanceCircuitFault_49 0 "Nomal" 1 "Fault" ;
VAL_ 2417487473 S2P_Bal_CSCSourceVoltFault_49 0 "Nomal" 1 "Fault" ;
VAL_ 2417487473 S2P_Bal_CellVoltOverFault_49 0 "Nomal" 1 "Fault" ;
VAL_ 2417487473 S2P_Bal_CellVoltLowFault_49 0 "Nomal" 1 "Fault" ;
VAL_ 2417487473 S2P_Bal_CSCPCBTempFault_49 0 "Nomal" 1 "Fault" ;
VAL_ 2417487473 S2P_Bal_CSCSourceCurrLowFault_49 0 "Nomal" 1 "Fault" ;
VAL_ 2417487473 S2P_Bal_CSCSourceCurrOvrFault_49 0 "Nomal" 1 "Fault" ;
VAL_ 2417487474 S2P_Bal_CSCNum_50 0 "No CSC" 1 "CSC 1" 2 "CSC 2" 3 "CSC 3" 4 "CSC 4" 5 "CSC 5" 6 "CSC 6" 7 "CSC 7" 8 "CSC 8" 9 "CSC 9" 10 "CSC 10" 11 "CSC 11" 12 "CSC 12" 13 "CSC 13" 14 "CSC 14" 15 "CSC 15" 16 "CSC 16" 17 "CSC 17" 18 "CSC 18" 19 "CSC 19" 20 "CSC 20" 21 "CSC 21" 22 "CSC 22" 23 "CSC 23" 24 "CSC 24" 25 "CSC 25" 26 "CSC 26" 27 "CSC 27" 28 "CSC 28" 29 "CSC 29" 30 "CSC 30" 31 "CSC 31" ;
VAL_ 2417487474 S2P_Bal_CellNum_50 1 "Cell 1" 2 "Cell 2" 3 "Cell 3" 4 "Cell 4" 5 "Cell 5" 6 "Cell 6" 7 "Cell 7" 8 "Cell 8" 9 "Cell 9" 10 "Cell 10" 11 "Cell 11" 12 "Cell 12" 13 "Cell 13" 14 "Cell 14" 15 "Cell 15" 16 "Cell 16" 63 "Null" ;
VAL_ 2417487474 S2P_Bal_Type_50 0 "Balance stop" 1 "charge Balance" 2 "discharge Balance" ;
VAL_ 2417487474 S2P_Bal_TypeLevel_50 0 "Not Balance" 1 "Low end Balance" 2 "High end Balance" 3 "Force Balance" ;
VAL_ 2417487474 S2P_Bal_SystemStatus_50 0 "Not Static" 1 "Staic Balance" 2 "Discharge false Balance" ;
VAL_ 2417487474 S2P_Bal_Strategy_50 0 "Active Balance" 1 "Passive Static" ;
VAL_ 2417487474 S2P_Bal_ForceBalMode_50 1 "Base on time " 2 "Base on Target Vol" 3 "Base on Ave Vol" ;
VAL_ 2417487474 S2P_Bal_CellTempFault_50 0 "Nomal" 1 "Fault" ;
VAL_ 2417487474 S2P_Bal_CellVoltFail_50 0 "Nomal" 1 "Fault" ;
VAL_ 2417487474 S2P_Bal_CloseBalInstruct_50 0 "Nomal" 1 "Fault" ;
VAL_ 2417487474 S2P_Bal_CCanTimeOut_50 0 "Nomal" 1 "Fault" ;
VAL_ 2417487474 S2P_Bal_CellOffLine_50 0 "Nomal" 1 "Fault" ;
VAL_ 2417487474 S2P_Bal_BalanceCircuitFault_50 0 "Nomal" 1 "Fault" ;
VAL_ 2417487474 S2P_Bal_CSCSourceVoltFault_50 0 "Nomal" 1 "Fault" ;
VAL_ 2417487474 S2P_Bal_CellVoltOverFault_50 0 "Nomal" 1 "Fault" ;
VAL_ 2417487474 S2P_Bal_CellVoltLowFault_50 0 "Nomal" 1 "Fault" ;
VAL_ 2417487474 S2P_Bal_CSCPCBTempFault_50 0 "Nomal" 1 "Fault" ;
VAL_ 2417487474 S2P_Bal_CSCSourceCurrLowFault_50 0 "Nomal" 1 "Fault" ;
VAL_ 2417487474 S2P_Bal_CSCSourceCurrOvrFault_50 0 "Nomal" 1 "Fault" ;
VAL_ 2417487475 S2P_Bal_CSCNum_51 0 "No CSC" 1 "CSC 1" 2 "CSC 2" 3 "CSC 3" 4 "CSC 4" 5 "CSC 5" 6 "CSC 6" 7 "CSC 7" 8 "CSC 8" 9 "CSC 9" 10 "CSC 10" 11 "CSC 11" 12 "CSC 12" 13 "CSC 13" 14 "CSC 14" 15 "CSC 15" 16 "CSC 16" 17 "CSC 17" 18 "CSC 18" 19 "CSC 19" 20 "CSC 20" 21 "CSC 21" 22 "CSC 22" 23 "CSC 23" 24 "CSC 24" 25 "CSC 25" 26 "CSC 26" 27 "CSC 27" 28 "CSC 28" 29 "CSC 29" 30 "CSC 30" 31 "CSC 31" ;
VAL_ 2417487475 S2P_Bal_CellNum_51 1 "Cell 1" 2 "Cell 2" 3 "Cell 3" 4 "Cell 4" 5 "Cell 5" 6 "Cell 6" 7 "Cell 7" 8 "Cell 8" 9 "Cell 9" 10 "Cell 10" 11 "Cell 11" 12 "Cell 12" 13 "Cell 13" 14 "Cell 14" 15 "Cell 15" 16 "Cell 16" 63 "Null" ;
VAL_ 2417487475 S2P_Bal_Type_51 0 "Balance stop" 1 "charge Balance" 2 "discharge Balance" ;
VAL_ 2417487475 S2P_Bal_TypeLevel_51 0 "Not Balance" 1 "Low end Balance" 2 "High end Balance" 3 "Force Balance" ;
VAL_ 2417487475 S2P_Bal_SystemStatus_51 0 "Not Static" 1 "Staic Balance" 2 "Discharge false Balance" ;
VAL_ 2417487475 S2P_Bal_Strategy_51 0 "Active Balance" 1 "Passive Static" ;
VAL_ 2417487475 S2P_Bal_ForceBalMode_51 1 "Base on time " 2 "Base on Target Vol" 3 "Base on Ave Vol" ;
VAL_ 2417487475 S2P_Bal_CellTempFault_51 0 "Nomal" 1 "Fault" ;
VAL_ 2417487475 S2P_Bal_CellVoltFail_51 0 "Nomal" 1 "Fault" ;
VAL_ 2417487475 S2P_Bal_CloseBalInstruct_51 0 "Nomal" 1 "Fault" ;
VAL_ 2417487475 S2P_Bal_CCanTimeOut_51 0 "Nomal" 1 "Fault" ;
VAL_ 2417487475 S2P_Bal_CellOffLine_51 0 "Nomal" 1 "Fault" ;
VAL_ 2417487475 S2P_Bal_BalanceCircuitFault_51 0 "Nomal" 1 "Fault" ;
VAL_ 2417487475 S2P_Bal_CSCSourceVoltFault_51 0 "Nomal" 1 "Fault" ;
VAL_ 2417487475 S2P_Bal_CellVoltOverFault_51 0 "Nomal" 1 "Fault" ;
VAL_ 2417487475 S2P_Bal_CellVoltLowFault_51 0 "Nomal" 1 "Fault" ;
VAL_ 2417487475 S2P_Bal_CSCPCBTempFault_51 0 "Nomal" 1 "Fault" ;
VAL_ 2417487475 S2P_Bal_CSCSourceCurrLowFault_51 0 "Nomal" 1 "Fault" ;
VAL_ 2417487475 S2P_Bal_CSCSourceCurrOvrFault_51 0 "Nomal" 1 "Fault" ;
VAL_ 2417487476 S2P_Bal_CSCNum_52 0 "No CSC" 1 "CSC 1" 2 "CSC 2" 3 "CSC 3" 4 "CSC 4" 5 "CSC 5" 6 "CSC 6" 7 "CSC 7" 8 "CSC 8" 9 "CSC 9" 10 "CSC 10" 11 "CSC 11" 12 "CSC 12" 13 "CSC 13" 14 "CSC 14" 15 "CSC 15" 16 "CSC 16" 17 "CSC 17" 18 "CSC 18" 19 "CSC 19" 20 "CSC 20" 21 "CSC 21" 22 "CSC 22" 23 "CSC 23" 24 "CSC 24" 25 "CSC 25" 26 "CSC 26" 27 "CSC 27" 28 "CSC 28" 29 "CSC 29" 30 "CSC 30" 31 "CSC 31" ;
VAL_ 2417487476 S2P_Bal_CellNum_52 1 "Cell 1" 2 "Cell 2" 3 "Cell 3" 4 "Cell 4" 5 "Cell 5" 6 "Cell 6" 7 "Cell 7" 8 "Cell 8" 9 "Cell 9" 10 "Cell 10" 11 "Cell 11" 12 "Cell 12" 13 "Cell 13" 14 "Cell 14" 15 "Cell 15" 16 "Cell 16" 63 "Null" ;
VAL_ 2417487476 S2P_Bal_Type_52 0 "Balance stop" 1 "charge Balance" 2 "discharge Balance" ;
VAL_ 2417487476 S2P_Bal_TypeLevel_52 0 "Not Balance" 1 "Low end Balance" 2 "High end Balance" 3 "Force Balance" ;
VAL_ 2417487476 S2P_Bal_SystemStatus_52 0 "Not Static" 1 "Staic Balance" 2 "Discharge false Balance" ;
VAL_ 2417487476 S2P_Bal_Strategy_52 0 "Active Balance" 1 "Passive Static" ;
VAL_ 2417487476 S2P_Bal_ForceBalMode_52 1 "Base on time " 2 "Base on Target Vol" 3 "Base on Ave Vol" ;
VAL_ 2417487476 S2P_Bal_CellTempFault_52 0 "Nomal" 1 "Fault" ;
VAL_ 2417487476 S2P_Bal_CellVoltFail_52 0 "Nomal" 1 "Fault" ;
VAL_ 2417487476 S2P_Bal_CloseBalInstruct_52 0 "Nomal" 1 "Fault" ;
VAL_ 2417487476 S2P_Bal_CCanTimeOut_52 0 "Nomal" 1 "Fault" ;
VAL_ 2417487476 S2P_Bal_CellOffLine_52 0 "Nomal" 1 "Fault" ;
VAL_ 2417487476 S2P_Bal_BalanceCircuitFault_52 0 "Nomal" 1 "Fault" ;
VAL_ 2417487476 S2P_Bal_CSCSourceVoltFault_52 0 "Nomal" 1 "Fault" ;
VAL_ 2417487476 S2P_Bal_CellVoltOverFault_52 0 "Nomal" 1 "Fault" ;
VAL_ 2417487476 S2P_Bal_CellVoltLowFault_52 0 "Nomal" 1 "Fault" ;
VAL_ 2417487476 S2P_Bal_CSCPCBTempFault_52 0 "Nomal" 1 "Fault" ;
VAL_ 2417487476 S2P_Bal_CSCSourceCurrLowFault_52 0 "Nomal" 1 "Fault" ;
VAL_ 2417487476 S2P_Bal_CSCSourceCurrOvrFault_52 0 "Nomal" 1 "Fault" ;
VAL_ 2417487477 S2P_Bal_CSCNum_53 0 "No CSC" 1 "CSC 1" 2 "CSC 2" 3 "CSC 3" 4 "CSC 4" 5 "CSC 5" 6 "CSC 6" 7 "CSC 7" 8 "CSC 8" 9 "CSC 9" 10 "CSC 10" 11 "CSC 11" 12 "CSC 12" 13 "CSC 13" 14 "CSC 14" 15 "CSC 15" 16 "CSC 16" 17 "CSC 17" 18 "CSC 18" 19 "CSC 19" 20 "CSC 20" 21 "CSC 21" 22 "CSC 22" 23 "CSC 23" 24 "CSC 24" 25 "CSC 25" 26 "CSC 26" 27 "CSC 27" 28 "CSC 28" 29 "CSC 29" 30 "CSC 30" 31 "CSC 31" ;
VAL_ 2417487477 S2P_Bal_CellNum_53 1 "Cell 1" 2 "Cell 2" 3 "Cell 3" 4 "Cell 4" 5 "Cell 5" 6 "Cell 6" 7 "Cell 7" 8 "Cell 8" 9 "Cell 9" 10 "Cell 10" 11 "Cell 11" 12 "Cell 12" 13 "Cell 13" 14 "Cell 14" 15 "Cell 15" 16 "Cell 16" 63 "Null" ;
VAL_ 2417487477 S2P_Bal_Type_53 0 "Balance stop" 1 "charge Balance" 2 "discharge Balance" ;
VAL_ 2417487477 S2P_Bal_TypeLevel_53 0 "Not Balance" 1 "Low end Balance" 2 "High end Balance" 3 "Force Balance" ;
VAL_ 2417487477 S2P_Bal_SystemStatus_53 0 "Not Static" 1 "Staic Balance" 2 "Discharge false Balance" ;
VAL_ 2417487477 S2P_Bal_Strategy_53 0 "Active Balance" 1 "Passive Static" ;
VAL_ 2417487477 S2P_Bal_ForceBalMode_53 1 "Base on time " 2 "Base on Target Vol" 3 "Base on Ave Vol" ;
VAL_ 2417487477 S2P_Bal_CellTempFault_53 0 "Nomal" 1 "Fault" ;
VAL_ 2417487477 S2P_Bal_CellVoltFail_53 0 "Nomal" 1 "Fault" ;
VAL_ 2417487477 S2P_Bal_CloseBalInstruct_53 0 "Nomal" 1 "Fault" ;
VAL_ 2417487477 S2P_Bal_CCanTimeOut_53 0 "Nomal" 1 "Fault" ;
VAL_ 2417487477 S2P_Bal_CellOffLine_53 0 "Nomal" 1 "Fault" ;
VAL_ 2417487477 S2P_Bal_BalanceCircuitFault_53 0 "Nomal" 1 "Fault" ;
VAL_ 2417487477 S2P_Bal_CSCSourceVoltFault_53 0 "Nomal" 1 "Fault" ;
VAL_ 2417487477 S2P_Bal_CellVoltOverFault_53 0 "Nomal" 1 "Fault" ;
VAL_ 2417487477 S2P_Bal_CellVoltLowFault_53 0 "Nomal" 1 "Fault" ;
VAL_ 2417487477 S2P_Bal_CSCPCBTempFault_53 0 "Nomal" 1 "Fault" ;
VAL_ 2417487477 S2P_Bal_CSCSourceCurrLowFault_53 0 "Nomal" 1 "Fault" ;
VAL_ 2417487477 S2P_Bal_CSCSourceCurrOvrFault_53 0 "Nomal" 1 "Fault" ;
VAL_ 2417487478 S2P_Bal_CSCNum_54 0 "No CSC" 1 "CSC 1" 2 "CSC 2" 3 "CSC 3" 4 "CSC 4" 5 "CSC 5" 6 "CSC 6" 7 "CSC 7" 8 "CSC 8" 9 "CSC 9" 10 "CSC 10" 11 "CSC 11" 12 "CSC 12" 13 "CSC 13" 14 "CSC 14" 15 "CSC 15" 16 "CSC 16" 17 "CSC 17" 18 "CSC 18" 19 "CSC 19" 20 "CSC 20" 21 "CSC 21" 22 "CSC 22" 23 "CSC 23" 24 "CSC 24" 25 "CSC 25" 26 "CSC 26" 27 "CSC 27" 28 "CSC 28" 29 "CSC 29" 30 "CSC 30" 31 "CSC 31" ;
VAL_ 2417487478 S2P_Bal_CellNum_54 1 "Cell 1" 2 "Cell 2" 3 "Cell 3" 4 "Cell 4" 5 "Cell 5" 6 "Cell 6" 7 "Cell 7" 8 "Cell 8" 9 "Cell 9" 10 "Cell 10" 11 "Cell 11" 12 "Cell 12" 13 "Cell 13" 14 "Cell 14" 15 "Cell 15" 16 "Cell 16" 63 "Null" ;
VAL_ 2417487478 S2P_Bal_Type_54 0 "Balance stop" 1 "charge Balance" 2 "discharge Balance" ;
VAL_ 2417487478 S2P_Bal_TypeLevel_54 0 "Not Balance" 1 "Low end Balance" 2 "High end Balance" 3 "Force Balance" ;
VAL_ 2417487478 S2P_Bal_SystemStatus_54 0 "Not Static" 1 "Staic Balance" 2 "Discharge false Balance" ;
VAL_ 2417487478 S2P_Bal_Strategy_54 0 "Active Balance" 1 "Passive Static" ;
VAL_ 2417487478 S2P_Bal_ForceBalMode_54 1 "Base on time " 2 "Base on Target Vol" 3 "Base on Ave Vol" ;
VAL_ 2417487478 S2P_Bal_CellTempFault_54 0 "Nomal" 1 "Fault" ;
VAL_ 2417487478 S2P_Bal_CellVoltFail_54 0 "Nomal" 1 "Fault" ;
VAL_ 2417487478 S2P_Bal_CloseBalInstruct_54 0 "Nomal" 1 "Fault" ;
VAL_ 2417487478 S2P_Bal_CCanTimeOut_54 0 "Nomal" 1 "Fault" ;
VAL_ 2417487478 S2P_Bal_CellOffLine_54 0 "Nomal" 1 "Fault" ;
VAL_ 2417487478 S2P_Bal_BalanceCircuitFault_54 0 "Nomal" 1 "Fault" ;
VAL_ 2417487478 S2P_Bal_CSCSourceVoltFault_54 0 "Nomal" 1 "Fault" ;
VAL_ 2417487478 S2P_Bal_CellVoltOverFault_54 0 "Nomal" 1 "Fault" ;
VAL_ 2417487478 S2P_Bal_CellVoltLowFault_54 0 "Nomal" 1 "Fault" ;
VAL_ 2417487478 S2P_Bal_CSCPCBTempFault_54 0 "Nomal" 1 "Fault" ;
VAL_ 2417487478 S2P_Bal_CSCSourceCurrLowFault_54 0 "Nomal" 1 "Fault" ;
VAL_ 2417487478 S2P_Bal_CSCSourceCurrOvrFault_54 0 "Nomal" 1 "Fault" ;
VAL_ 2417487479 S2P_Bal_CSCNum_55 0 "No CSC" 1 "CSC 1" 2 "CSC 2" 3 "CSC 3" 4 "CSC 4" 5 "CSC 5" 6 "CSC 6" 7 "CSC 7" 8 "CSC 8" 9 "CSC 9" 10 "CSC 10" 11 "CSC 11" 12 "CSC 12" 13 "CSC 13" 14 "CSC 14" 15 "CSC 15" 16 "CSC 16" 17 "CSC 17" 18 "CSC 18" 19 "CSC 19" 20 "CSC 20" 21 "CSC 21" 22 "CSC 22" 23 "CSC 23" 24 "CSC 24" 25 "CSC 25" 26 "CSC 26" 27 "CSC 27" 28 "CSC 28" 29 "CSC 29" 30 "CSC 30" 31 "CSC 31" ;
VAL_ 2417487479 S2P_Bal_CellNum_55 1 "Cell 1" 2 "Cell 2" 3 "Cell 3" 4 "Cell 4" 5 "Cell 5" 6 "Cell 6" 7 "Cell 7" 8 "Cell 8" 9 "Cell 9" 10 "Cell 10" 11 "Cell 11" 12 "Cell 12" 13 "Cell 13" 14 "Cell 14" 15 "Cell 15" 16 "Cell 16" 63 "Null" ;
VAL_ 2417487479 S2P_Bal_Type_55 0 "Balance stop" 1 "charge Balance" 2 "discharge Balance" ;
VAL_ 2417487479 S2P_Bal_TypeLevel_55 0 "Not Balance" 1 "Low end Balance" 2 "High end Balance" 3 "Force Balance" ;
VAL_ 2417487479 S2P_Bal_SystemStatus_55 0 "Not Static" 1 "Staic Balance" 2 "Discharge false Balance" ;
VAL_ 2417487479 S2P_Bal_Strategy_55 0 "Active Balance" 1 "Passive Static" ;
VAL_ 2417487479 S2P_Bal_ForceBalMode_55 1 "Base on time " 2 "Base on Target Vol" 3 "Base on Ave Vol" ;
VAL_ 2417487479 S2P_Bal_CellTempFault_55 0 "Nomal" 1 "Fault" ;
VAL_ 2417487479 S2P_Bal_CellVoltFail_55 0 "Nomal" 1 "Fault" ;
VAL_ 2417487479 S2P_Bal_CloseBalInstruct_55 0 "Nomal" 1 "Fault" ;
VAL_ 2417487479 S2P_Bal_CCanTimeOut_55 0 "Nomal" 1 "Fault" ;
VAL_ 2417487479 S2P_Bal_CellOffLine_55 0 "Nomal" 1 "Fault" ;
VAL_ 2417487479 S2P_Bal_BalanceCircuitFault_55 0 "Nomal" 1 "Fault" ;
VAL_ 2417487479 S2P_Bal_CSCSourceVoltFault_55 0 "Nomal" 1 "Fault" ;
VAL_ 2417487479 S2P_Bal_CellVoltOverFault_55 0 "Nomal" 1 "Fault" ;
VAL_ 2417487479 S2P_Bal_CellVoltLowFault_55 0 "Nomal" 1 "Fault" ;
VAL_ 2417487479 S2P_Bal_CSCPCBTempFault_55 0 "Nomal" 1 "Fault" ;
VAL_ 2417487479 S2P_Bal_CSCSourceCurrLowFault_55 0 "Nomal" 1 "Fault" ;
VAL_ 2417487479 S2P_Bal_CSCSourceCurrOvrFault_55 0 "Nomal" 1 "Fault" ;
VAL_ 2417487480 S2P_Bal_CSCNum_56 0 "No CSC" 1 "CSC 1" 2 "CSC 2" 3 "CSC 3" 4 "CSC 4" 5 "CSC 5" 6 "CSC 6" 7 "CSC 7" 8 "CSC 8" 9 "CSC 9" 10 "CSC 10" 11 "CSC 11" 12 "CSC 12" 13 "CSC 13" 14 "CSC 14" 15 "CSC 15" 16 "CSC 16" 17 "CSC 17" 18 "CSC 18" 19 "CSC 19" 20 "CSC 20" 21 "CSC 21" 22 "CSC 22" 23 "CSC 23" 24 "CSC 24" 25 "CSC 25" 26 "CSC 26" 27 "CSC 27" 28 "CSC 28" 29 "CSC 29" 30 "CSC 30" 31 "CSC 31" ;
VAL_ 2417487480 S2P_Bal_CellNum_56 1 "Cell 1" 2 "Cell 2" 3 "Cell 3" 4 "Cell 4" 5 "Cell 5" 6 "Cell 6" 7 "Cell 7" 8 "Cell 8" 9 "Cell 9" 10 "Cell 10" 11 "Cell 11" 12 "Cell 12" 13 "Cell 13" 14 "Cell 14" 15 "Cell 15" 16 "Cell 16" 63 "Null" ;
VAL_ 2417487480 S2P_Bal_Type_56 0 "Balance stop" 1 "charge Balance" 2 "discharge Balance" ;
VAL_ 2417487480 S2P_Bal_TypeLevel_56 0 "Not Balance" 1 "Low end Balance" 2 "High end Balance" 3 "Force Balance" ;
VAL_ 2417487480 S2P_Bal_SystemStatus_56 0 "Not Static" 1 "Staic Balance" 2 "Discharge false Balance" ;
VAL_ 2417487480 S2P_Bal_Strategy_56 0 "Active Balance" 1 "Passive Static" ;
VAL_ 2417487480 S2P_Bal_ForceBalMode_56 1 "Base on time " 2 "Base on Target Vol" 3 "Base on Ave Vol" ;
VAL_ 2417487480 S2P_Bal_CellTempFault_56 0 "Nomal" 1 "Fault" ;
VAL_ 2417487480 S2P_Bal_CellVoltFail_56 0 "Nomal" 1 "Fault" ;
VAL_ 2417487480 S2P_Bal_CloseBalInstruct_56 0 "Nomal" 1 "Fault" ;
VAL_ 2417487480 S2P_Bal_CCanTimeOut_56 0 "Nomal" 1 "Fault" ;
VAL_ 2417487480 S2P_Bal_CellOffLine_56 0 "Nomal" 1 "Fault" ;
VAL_ 2417487480 S2P_Bal_BalanceCircuitFault_56 0 "Nomal" 1 "Fault" ;
VAL_ 2417487480 S2P_Bal_CSCSourceVoltFault_56 0 "Nomal" 1 "Fault" ;
VAL_ 2417487480 S2P_Bal_CellVoltOverFault_56 0 "Nomal" 1 "Fault" ;
VAL_ 2417487480 S2P_Bal_CellVoltLowFault_56 0 "Nomal" 1 "Fault" ;
VAL_ 2417487480 S2P_Bal_CSCPCBTempFault_56 0 "Nomal" 1 "Fault" ;
VAL_ 2417487480 S2P_Bal_CSCSourceCurrLowFault_56 0 "Nomal" 1 "Fault" ;
VAL_ 2417487480 S2P_Bal_CSCSourceCurrOvrFault_56 0 "Nomal" 1 "Fault" ;
VAL_ 2417487481 S2P_Bal_CSCNum_57 0 "No CSC" 1 "CSC 1" 2 "CSC 2" 3 "CSC 3" 4 "CSC 4" 5 "CSC 5" 6 "CSC 6" 7 "CSC 7" 8 "CSC 8" 9 "CSC 9" 10 "CSC 10" 11 "CSC 11" 12 "CSC 12" 13 "CSC 13" 14 "CSC 14" 15 "CSC 15" 16 "CSC 16" 17 "CSC 17" 18 "CSC 18" 19 "CSC 19" 20 "CSC 20" 21 "CSC 21" 22 "CSC 22" 23 "CSC 23" 24 "CSC 24" 25 "CSC 25" 26 "CSC 26" 27 "CSC 27" 28 "CSC 28" 29 "CSC 29" 30 "CSC 30" 31 "CSC 31" ;
VAL_ 2417487481 S2P_Bal_CellNum_57 1 "Cell 1" 2 "Cell 2" 3 "Cell 3" 4 "Cell 4" 5 "Cell 5" 6 "Cell 6" 7 "Cell 7" 8 "Cell 8" 9 "Cell 9" 10 "Cell 10" 11 "Cell 11" 12 "Cell 12" 13 "Cell 13" 14 "Cell 14" 15 "Cell 15" 16 "Cell 16" 63 "Null" ;
VAL_ 2417487481 S2P_Bal_Type_57 0 "Balance stop" 1 "charge Balance" 2 "discharge Balance" ;
VAL_ 2417487481 S2P_Bal_TypeLevel_57 0 "Not Balance" 1 "Low end Balance" 2 "High end Balance" 3 "Force Balance" ;
VAL_ 2417487481 S2P_Bal_SystemStatus_57 0 "Not Static" 1 "Staic Balance" 2 "Discharge false Balance" ;
VAL_ 2417487481 S2P_Bal_Strategy_57 0 "Active Balance" 1 "Passive Static" ;
VAL_ 2417487481 S2P_Bal_ForceBalMode_57 1 "Base on time " 2 "Base on Target Vol" 3 "Base on Ave Vol" ;
VAL_ 2417487481 S2P_Bal_CellTempFault_57 0 "Nomal" 1 "Fault" ;
VAL_ 2417487481 S2P_Bal_CellVoltFail_57 0 "Nomal" 1 "Fault" ;
VAL_ 2417487481 S2P_Bal_CloseBalInstruct_57 0 "Nomal" 1 "Fault" ;
VAL_ 2417487481 S2P_Bal_CCanTimeOut_57 0 "Nomal" 1 "Fault" ;
VAL_ 2417487481 S2P_Bal_CellOffLine_57 0 "Nomal" 1 "Fault" ;
VAL_ 2417487481 S2P_Bal_BalanceCircuitFault_57 0 "Nomal" 1 "Fault" ;
VAL_ 2417487481 S2P_Bal_CSCSourceVoltFault_57 0 "Nomal" 1 "Fault" ;
VAL_ 2417487481 S2P_Bal_CellVoltOverFault_57 0 "Nomal" 1 "Fault" ;
VAL_ 2417487481 S2P_Bal_CellVoltLowFault_57 0 "Nomal" 1 "Fault" ;
VAL_ 2417487481 S2P_Bal_CSCPCBTempFault_57 0 "Nomal" 1 "Fault" ;
VAL_ 2417487481 S2P_Bal_CSCSourceCurrLowFault_57 0 "Nomal" 1 "Fault" ;
VAL_ 2417487481 S2P_Bal_CSCSourceCurrOvrFault_57 0 "Nomal" 1 "Fault" ;
VAL_ 2417487482 S2P_Bal_CSCNum_58 0 "No CSC" 1 "CSC 1" 2 "CSC 2" 3 "CSC 3" 4 "CSC 4" 5 "CSC 5" 6 "CSC 6" 7 "CSC 7" 8 "CSC 8" 9 "CSC 9" 10 "CSC 10" 11 "CSC 11" 12 "CSC 12" 13 "CSC 13" 14 "CSC 14" 15 "CSC 15" 16 "CSC 16" 17 "CSC 17" 18 "CSC 18" 19 "CSC 19" 20 "CSC 20" 21 "CSC 21" 22 "CSC 22" 23 "CSC 23" 24 "CSC 24" 25 "CSC 25" 26 "CSC 26" 27 "CSC 27" 28 "CSC 28" 29 "CSC 29" 30 "CSC 30" 31 "CSC 31" ;
VAL_ 2417487482 S2P_Bal_CellNum_58 1 "Cell 1" 2 "Cell 2" 3 "Cell 3" 4 "Cell 4" 5 "Cell 5" 6 "Cell 6" 7 "Cell 7" 8 "Cell 8" 9 "Cell 9" 10 "Cell 10" 11 "Cell 11" 12 "Cell 12" 13 "Cell 13" 14 "Cell 14" 15 "Cell 15" 16 "Cell 16" 63 "Null" ;
VAL_ 2417487482 S2P_Bal_Type_58 0 "Balance stop" 1 "charge Balance" 2 "discharge Balance" ;
VAL_ 2417487482 S2P_Bal_TypeLevel_58 0 "Not Balance" 1 "Low end Balance" 2 "High end Balance" 3 "Force Balance" ;
VAL_ 2417487482 S2P_Bal_SystemStatus_58 0 "Not Static" 1 "Staic Balance" 2 "Discharge false Balance" ;
VAL_ 2417487482 S2P_Bal_Strategy_58 0 "Active Balance" 1 "Passive Static" ;
VAL_ 2417487482 S2P_Bal_ForceBalMode_58 1 "Base on time " 2 "Base on Target Vol" 3 "Base on Ave Vol" ;
VAL_ 2417487482 S2P_Bal_CellTempFault_58 0 "Nomal" 1 "Fault" ;
VAL_ 2417487482 S2P_Bal_CellVoltFail_58 0 "Nomal" 1 "Fault" ;
VAL_ 2417487482 S2P_Bal_CloseBalInstruct_58 0 "Nomal" 1 "Fault" ;
VAL_ 2417487482 S2P_Bal_CCanTimeOut_58 0 "Nomal" 1 "Fault" ;
VAL_ 2417487482 S2P_Bal_CellOffLine_58 0 "Nomal" 1 "Fault" ;
VAL_ 2417487482 S2P_Bal_BalanceCircuitFault_58 0 "Nomal" 1 "Fault" ;
VAL_ 2417487482 S2P_Bal_CSCSourceVoltFault_58 0 "Nomal" 1 "Fault" ;
VAL_ 2417487482 S2P_Bal_CellVoltOverFault_58 0 "Nomal" 1 "Fault" ;
VAL_ 2417487482 S2P_Bal_CellVoltLowFault_58 0 "Nomal" 1 "Fault" ;
VAL_ 2417487482 S2P_Bal_CSCPCBTempFault_58 0 "Nomal" 1 "Fault" ;
VAL_ 2417487482 S2P_Bal_CSCSourceCurrLowFault_58 0 "Nomal" 1 "Fault" ;
VAL_ 2417487482 S2P_Bal_CSCSourceCurrOvrFault_58 0 "Nomal" 1 "Fault" ;
VAL_ 2417487483 S2P_Bal_CSCNum_59 0 "No CSC" 1 "CSC 1" 2 "CSC 2" 3 "CSC 3" 4 "CSC 4" 5 "CSC 5" 6 "CSC 6" 7 "CSC 7" 8 "CSC 8" 9 "CSC 9" 10 "CSC 10" 11 "CSC 11" 12 "CSC 12" 13 "CSC 13" 14 "CSC 14" 15 "CSC 15" 16 "CSC 16" 17 "CSC 17" 18 "CSC 18" 19 "CSC 19" 20 "CSC 20" 21 "CSC 21" 22 "CSC 22" 23 "CSC 23" 24 "CSC 24" 25 "CSC 25" 26 "CSC 26" 27 "CSC 27" 28 "CSC 28" 29 "CSC 29" 30 "CSC 30" 31 "CSC 31" ;
VAL_ 2417487483 S2P_Bal_CellNum_59 1 "Cell 1" 2 "Cell 2" 3 "Cell 3" 4 "Cell 4" 5 "Cell 5" 6 "Cell 6" 7 "Cell 7" 8 "Cell 8" 9 "Cell 9" 10 "Cell 10" 11 "Cell 11" 12 "Cell 12" 13 "Cell 13" 14 "Cell 14" 15 "Cell 15" 16 "Cell 16" 63 "Null" ;
VAL_ 2417487483 S2P_Bal_Type_59 0 "Balance stop" 1 "charge Balance" 2 "discharge Balance" ;
VAL_ 2417487483 S2P_Bal_TypeLevel_59 0 "Not Balance" 1 "Low end Balance" 2 "High end Balance" 3 "Force Balance" ;
VAL_ 2417487483 S2P_Bal_SystemStatus_59 0 "Not Static" 1 "Staic Balance" 2 "Discharge false Balance" ;
VAL_ 2417487483 S2P_Bal_Strategy_59 0 "Active Balance" 1 "Passive Static" ;
VAL_ 2417487483 S2P_Bal_ForceBalMode_59 1 "Base on time " 2 "Base on Target Vol" 3 "Base on Ave Vol" ;
VAL_ 2417487483 S2P_Bal_CellTempFault_59 0 "Nomal" 1 "Fault" ;
VAL_ 2417487483 S2P_Bal_CellVoltFail_59 0 "Nomal" 1 "Fault" ;
VAL_ 2417487483 S2P_Bal_CloseBalInstruct_59 0 "Nomal" 1 "Fault" ;
VAL_ 2417487483 S2P_Bal_CCanTimeOut_59 0 "Nomal" 1 "Fault" ;
VAL_ 2417487483 S2P_Bal_CellOffLine_59 0 "Nomal" 1 "Fault" ;
VAL_ 2417487483 S2P_Bal_BalanceCircuitFault_59 0 "Nomal" 1 "Fault" ;
VAL_ 2417487483 S2P_Bal_CSCSourceVoltFault_59 0 "Nomal" 1 "Fault" ;
VAL_ 2417487483 S2P_Bal_CellVoltOverFault_59 0 "Nomal" 1 "Fault" ;
VAL_ 2417487483 S2P_Bal_CellVoltLowFault_59 0 "Nomal" 1 "Fault" ;
VAL_ 2417487483 S2P_Bal_CSCPCBTempFault_59 0 "Nomal" 1 "Fault" ;
VAL_ 2417487483 S2P_Bal_CSCSourceCurrLowFault_59 0 "Nomal" 1 "Fault" ;
VAL_ 2417487483 S2P_Bal_CSCSourceCurrOvrFault_59 0 "Nomal" 1 "Fault" ;
VAL_ 2417487484 S2P_Bal_CSCNum_60 0 "No CSC" 1 "CSC 1" 2 "CSC 2" 3 "CSC 3" 4 "CSC 4" 5 "CSC 5" 6 "CSC 6" 7 "CSC 7" 8 "CSC 8" 9 "CSC 9" 10 "CSC 10" 11 "CSC 11" 12 "CSC 12" 13 "CSC 13" 14 "CSC 14" 15 "CSC 15" 16 "CSC 16" 17 "CSC 17" 18 "CSC 18" 19 "CSC 19" 20 "CSC 20" 21 "CSC 21" 22 "CSC 22" 23 "CSC 23" 24 "CSC 24" 25 "CSC 25" 26 "CSC 26" 27 "CSC 27" 28 "CSC 28" 29 "CSC 29" 30 "CSC 30" 31 "CSC 31" ;
VAL_ 2417487484 S2P_Bal_CellNum_60 1 "Cell 1" 2 "Cell 2" 3 "Cell 3" 4 "Cell 4" 5 "Cell 5" 6 "Cell 6" 7 "Cell 7" 8 "Cell 8" 9 "Cell 9" 10 "Cell 10" 11 "Cell 11" 12 "Cell 12" 13 "Cell 13" 14 "Cell 14" 15 "Cell 15" 16 "Cell 16" 63 "Null" ;
VAL_ 2417487484 S2P_Bal_Type_60 0 "Balance stop" 1 "charge Balance" 2 "discharge Balance" ;
VAL_ 2417487484 S2P_Bal_TypeLevel_60 0 "Not Balance" 1 "Low end Balance" 2 "High end Balance" 3 "Force Balance" ;
VAL_ 2417487484 S2P_Bal_SystemStatus_60 0 "Not Static" 1 "Staic Balance" 2 "Discharge false Balance" ;
VAL_ 2417487484 S2P_Bal_Strategy_60 0 "Active Balance" 1 "Passive Static" ;
VAL_ 2417487484 S2P_Bal_ForceBalMode_60 1 "Base on time " 2 "Base on Target Vol" 3 "Base on Ave Vol" ;
VAL_ 2417487484 S2P_Bal_CellTempFault_60 0 "Nomal" 1 "Fault" ;
VAL_ 2417487484 S2P_Bal_CellVoltFail_60 0 "Nomal" 1 "Fault" ;
VAL_ 2417487484 S2P_Bal_CloseBalInstruct_60 0 "Nomal" 1 "Fault" ;
VAL_ 2417487484 S2P_Bal_CCanTimeOut_60 0 "Nomal" 1 "Fault" ;
VAL_ 2417487484 S2P_Bal_CellOffLine_60 0 "Nomal" 1 "Fault" ;
VAL_ 2417487484 S2P_Bal_BalanceCircuitFault_60 0 "Nomal" 1 "Fault" ;
VAL_ 2417487484 S2P_Bal_CSCSourceVoltFault_60 0 "Nomal" 1 "Fault" ;
VAL_ 2417487484 S2P_Bal_CellVoltOverFault_60 0 "Nomal" 1 "Fault" ;
VAL_ 2417487484 S2P_Bal_CellVoltLowFault_60 0 "Nomal" 1 "Fault" ;
VAL_ 2417487484 S2P_Bal_CSCPCBTempFault_60 0 "Nomal" 1 "Fault" ;
VAL_ 2417487484 S2P_Bal_CSCSourceCurrLowFault_60 0 "Nomal" 1 "Fault" ;
VAL_ 2417487484 S2P_Bal_CSCSourceCurrOvrFault_60 0 "Nomal" 1 "Fault" ;
VAL_ 2417487485 S2P_Bal_CSCNum_61 0 "No CSC" 1 "CSC 1" 2 "CSC 2" 3 "CSC 3" 4 "CSC 4" 5 "CSC 5" 6 "CSC 6" 7 "CSC 7" 8 "CSC 8" 9 "CSC 9" 10 "CSC 10" 11 "CSC 11" 12 "CSC 12" 13 "CSC 13" 14 "CSC 14" 15 "CSC 15" 16 "CSC 16" 17 "CSC 17" 18 "CSC 18" 19 "CSC 19" 20 "CSC 20" 21 "CSC 21" 22 "CSC 22" 23 "CSC 23" 24 "CSC 24" 25 "CSC 25" 26 "CSC 26" 27 "CSC 27" 28 "CSC 28" 29 "CSC 29" 30 "CSC 30" 31 "CSC 31" ;
VAL_ 2417487485 S2P_Bal_CellNum_61 1 "Cell 1" 2 "Cell 2" 3 "Cell 3" 4 "Cell 4" 5 "Cell 5" 6 "Cell 6" 7 "Cell 7" 8 "Cell 8" 9 "Cell 9" 10 "Cell 10" 11 "Cell 11" 12 "Cell 12" 13 "Cell 13" 14 "Cell 14" 15 "Cell 15" 16 "Cell 16" 63 "Null" ;
VAL_ 2417487485 S2P_Bal_Type_61 0 "Balance stop" 1 "charge Balance" 2 "discharge Balance" ;
VAL_ 2417487485 S2P_Bal_TypeLevel_61 0 "Not Balance" 1 "Low end Balance" 2 "High end Balance" 3 "Force Balance" ;
VAL_ 2417487485 S2P_Bal_SystemStatus_61 0 "Not Static" 1 "Staic Balance" 2 "Discharge false Balance" ;
VAL_ 2417487485 S2P_Bal_Strategy_61 0 "Active Balance" 1 "Passive Static" ;
VAL_ 2417487485 S2P_Bal_ForceBalMode_61 1 "Base on time " 2 "Base on Target Vol" 3 "Base on Ave Vol" ;
VAL_ 2417487485 S2P_Bal_CellTempFault_61 0 "Nomal" 1 "Fault" ;
VAL_ 2417487485 S2P_Bal_CellVoltFail_61 0 "Nomal" 1 "Fault" ;
VAL_ 2417487485 S2P_Bal_CloseBalInstruct_61 0 "Nomal" 1 "Fault" ;
VAL_ 2417487485 S2P_Bal_CCanTimeOut_61 0 "Nomal" 1 "Fault" ;
VAL_ 2417487485 S2P_Bal_CellOffLine_61 0 "Nomal" 1 "Fault" ;
VAL_ 2417487485 S2P_Bal_BalanceCircuitFault_61 0 "Nomal" 1 "Fault" ;
VAL_ 2417487485 S2P_Bal_CSCSourceVoltFault_61 0 "Nomal" 1 "Fault" ;
VAL_ 2417487485 S2P_Bal_CellVoltOverFault_61 0 "Nomal" 1 "Fault" ;
VAL_ 2417487485 S2P_Bal_CellVoltLowFault_61 0 "Nomal" 1 "Fault" ;
VAL_ 2417487485 S2P_Bal_CSCPCBTempFault_61 0 "Nomal" 1 "Fault" ;
VAL_ 2417487485 S2P_Bal_CSCSourceCurrLowFault_61 0 "Nomal" 1 "Fault" ;
VAL_ 2417487485 S2P_Bal_CSCSourceCurrOvrFault_61 0 "Nomal" 1 "Fault" ;
VAL_ 2417487486 S2P_Bal_CSCNum_62 0 "No CSC" 1 "CSC 1" 2 "CSC 2" 3 "CSC 3" 4 "CSC 4" 5 "CSC 5" 6 "CSC 6" 7 "CSC 7" 8 "CSC 8" 9 "CSC 9" 10 "CSC 10" 11 "CSC 11" 12 "CSC 12" 13 "CSC 13" 14 "CSC 14" 15 "CSC 15" 16 "CSC 16" 17 "CSC 17" 18 "CSC 18" 19 "CSC 19" 20 "CSC 20" 21 "CSC 21" 22 "CSC 22" 23 "CSC 23" 24 "CSC 24" 25 "CSC 25" 26 "CSC 26" 27 "CSC 27" 28 "CSC 28" 29 "CSC 29" 30 "CSC 30" 31 "CSC 31" ;
VAL_ 2417487486 S2P_Bal_CellNum_62 1 "Cell 1" 2 "Cell 2" 3 "Cell 3" 4 "Cell 4" 5 "Cell 5" 6 "Cell 6" 7 "Cell 7" 8 "Cell 8" 9 "Cell 9" 10 "Cell 10" 11 "Cell 11" 12 "Cell 12" 13 "Cell 13" 14 "Cell 14" 15 "Cell 15" 16 "Cell 16" 63 "Null" ;
VAL_ 2417487486 S2P_Bal_Type_62 0 "Balance stop" 1 "charge Balance" 2 "discharge Balance" ;
VAL_ 2417487486 S2P_Bal_TypeLevel_62 0 "Not Balance" 1 "Low end Balance" 2 "High end Balance" 3 "Force Balance" ;
VAL_ 2417487486 S2P_Bal_SystemStatus_62 0 "Not Static" 1 "Staic Balance" 2 "Discharge false Balance" ;
VAL_ 2417487486 S2P_Bal_Strategy_62 0 "Active Balance" 1 "Passive Static" ;
VAL_ 2417487486 S2P_Bal_ForceBalMode_62 1 "Base on time " 2 "Base on Target Vol" 3 "Base on Ave Vol" ;
VAL_ 2417487486 S2P_Bal_CellTempFault_62 0 "Nomal" 1 "Fault" ;
VAL_ 2417487486 S2P_Bal_CellVoltFail_62 0 "Nomal" 1 "Fault" ;
VAL_ 2417487486 S2P_Bal_CloseBalInstruct_62 0 "Nomal" 1 "Fault" ;
VAL_ 2417487486 S2P_Bal_CCanTimeOut_62 0 "Nomal" 1 "Fault" ;
VAL_ 2417487486 S2P_Bal_CellOffLine_62 0 "Nomal" 1 "Fault" ;
VAL_ 2417487486 S2P_Bal_BalanceCircuitFault_62 0 "Nomal" 1 "Fault" ;
VAL_ 2417487486 S2P_Bal_CSCSourceVoltFault_62 0 "Nomal" 1 "Fault" ;
VAL_ 2417487486 S2P_Bal_CellVoltOverFault_62 0 "Nomal" 1 "Fault" ;
VAL_ 2417487486 S2P_Bal_CellVoltLowFault_62 0 "Nomal" 1 "Fault" ;
VAL_ 2417487486 S2P_Bal_CSCPCBTempFault_62 0 "Nomal" 1 "Fault" ;
VAL_ 2417487486 S2P_Bal_CSCSourceCurrLowFault_62 0 "Nomal" 1 "Fault" ;
VAL_ 2417487486 S2P_Bal_CSCSourceCurrOvrFault_62 0 "Nomal" 1 "Fault" ;
VAL_ 2417487487 S2P_Bal_CSCNum_63 0 "No CSC" 1 "CSC 1" 2 "CSC 2" 3 "CSC 3" 4 "CSC 4" 5 "CSC 5" 6 "CSC 6" 7 "CSC 7" 8 "CSC 8" 9 "CSC 9" 10 "CSC 10" 11 "CSC 11" 12 "CSC 12" 13 "CSC 13" 14 "CSC 14" 15 "CSC 15" 16 "CSC 16" 17 "CSC 17" 18 "CSC 18" 19 "CSC 19" 20 "CSC 20" 21 "CSC 21" 22 "CSC 22" 23 "CSC 23" 24 "CSC 24" 25 "CSC 25" 26 "CSC 26" 27 "CSC 27" 28 "CSC 28" 29 "CSC 29" 30 "CSC 30" 31 "CSC 31" ;
VAL_ 2417487487 S2P_Bal_CellNum_63 1 "Cell 1" 2 "Cell 2" 3 "Cell 3" 4 "Cell 4" 5 "Cell 5" 6 "Cell 6" 7 "Cell 7" 8 "Cell 8" 9 "Cell 9" 10 "Cell 10" 11 "Cell 11" 12 "Cell 12" 13 "Cell 13" 14 "Cell 14" 15 "Cell 15" 16 "Cell 16" 63 "Null" ;
VAL_ 2417487487 S2P_Bal_Type_63 0 "Balance stop" 1 "charge Balance" 2 "discharge Balance" ;
VAL_ 2417487487 S2P_Bal_TypeLevel_63 0 "Not Balance" 1 "Low end Balance" 2 "High end Balance" 3 "Force Balance" ;
VAL_ 2417487487 S2P_Bal_SystemStatus_63 0 "Not Static" 1 "Staic Balance" 2 "Discharge false Balance" ;
VAL_ 2417487487 S2P_Bal_Strategy_63 0 "Active Balance" 1 "Passive Static" ;
VAL_ 2417487487 S2P_Bal_ForceBalMode_63 1 "Base on time " 2 "Base on Target Vol" 3 "Base on Ave Vol" ;
VAL_ 2417487487 S2P_Bal_CellTempFault_63 0 "Nomal" 1 "Fault" ;
VAL_ 2417487487 S2P_Bal_CellVoltFail_63 0 "Nomal" 1 "Fault" ;
VAL_ 2417487487 S2P_Bal_CloseBalInstruct_63 0 "Nomal" 1 "Fault" ;
VAL_ 2417487487 S2P_Bal_CCanTimeOut_63 0 "Nomal" 1 "Fault" ;
VAL_ 2417487487 S2P_Bal_CellOffLine_63 0 "Nomal" 1 "Fault" ;
VAL_ 2417487487 S2P_Bal_BalanceCircuitFault_63 0 "Nomal" 1 "Fault" ;
VAL_ 2417487487 S2P_Bal_CSCSourceVoltFault_63 0 "Nomal" 1 "Fault" ;
VAL_ 2417487487 S2P_Bal_CellVoltOverFault_63 0 "Nomal" 1 "Fault" ;
VAL_ 2417487487 S2P_Bal_CellVoltLowFault_63 0 "Nomal" 1 "Fault" ;
VAL_ 2417487487 S2P_Bal_CSCPCBTempFault_63 0 "Nomal" 1 "Fault" ;
VAL_ 2417487487 S2P_Bal_CSCSourceCurrLowFault_63 0 "Nomal" 1 "Fault" ;
VAL_ 2417487487 S2P_Bal_CSCSourceCurrOvrFault_63 0 "Nomal" 1 "Fault" ;
VERSION ""

NS_ :

BS_:

BU_: MBMU PC SBMU IMM ETH DCDC LEMS

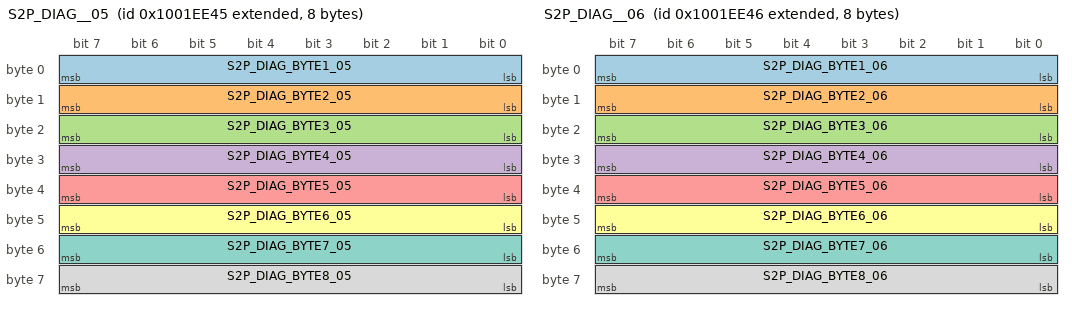
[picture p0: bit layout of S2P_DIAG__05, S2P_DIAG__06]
BO_ 2416045637 S2P_DIAG__05: 8 SBMU
 SG_ S2P_DIAG_BYTE1_05 : 0|8@1+ (1,0) [0|255] ""  PC
 SG_ S2P_DIAG_BYTE2_05 : 8|8@1+ (1,0) [0|255] ""  PC
 SG_ S2P_DIAG_BYTE3_05 : 16|8@1+ (1,0) [0|255] ""  PC
 SG_ S2P_DIAG_BYTE4_05 : 24|8@1+ (1,0) [0|255] ""  PC
 SG_ S2P_DIAG_BYTE5_05 : 32|8@1+ (1,0) [0|255] ""  PC
 SG_ S2P_DIAG_BYTE6_05 : 40|8@1+ (1,0) [0|255] ""  PC
 SG_ S2P_DIAG_BYTE7_05 : 48|8@1+ (1,0) [0|255] ""  PC
 SG_ S2P_DIAG_BYTE8_05 : 56|8@1+ (1,0) [0|255] ""  PC

BO_ 2416045638 S2P_DIAG__06: 8 SBMU
 SG_ S2P_DIAG_BYTE1_06 : 0|8@1+ (1,0) [0|255] ""  PC
 SG_ S2P_DIAG_BYTE2_06 : 8|8@1+ (1,0) [0|255] ""  PC
 SG_ S2P_DIAG_BYTE3_06 : 16|8@1+ (1,0) [0|255] ""  PC
 SG_ S2P_DIAG_BYTE4_06 : 24|8@1+ (1,0) [0|255] ""  PC
 SG_ S2P_DIAG_BYTE5_06 : 32|8@1+ (1,0) [0|255] ""  PC
 SG_ S2P_DIAG_BYTE6_06 : 40|8@1+ (1,0) [0|255] ""  PC
 SG_ S2P_DIAG_BYTE7_06 : 48|8@1+ (1,0) [0|255] ""  PC
 SG_ S2P_DIAG_BYTE8_06 : 56|8@1+ (1,0) [0|255] ""  PC

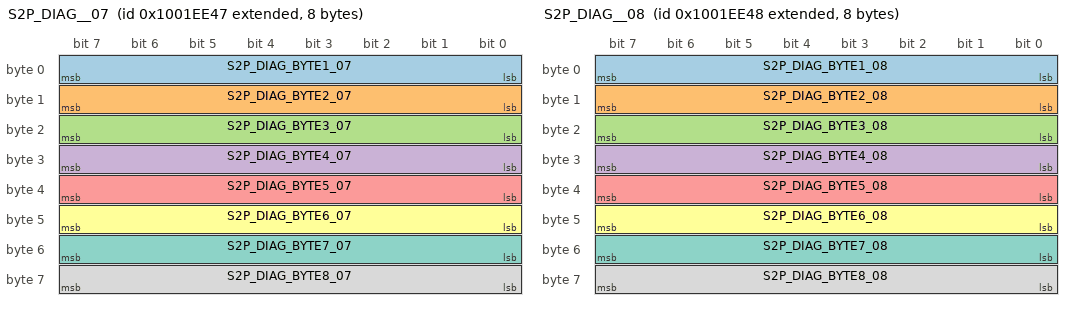
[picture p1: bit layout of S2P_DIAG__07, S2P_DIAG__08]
BO_ 2416045639 S2P_DIAG__07: 8 SBMU
 SG_ S2P_DIAG_BYTE1_07 : 0|8@1+ (1,0) [0|255] ""  PC
 SG_ S2P_DIAG_BYTE2_07 : 8|8@1+ (1,0) [0|255] ""  PC
 SG_ S2P_DIAG_BYTE3_07 : 16|8@1+ (1,0) [0|255] ""  PC
 SG_ S2P_DIAG_BYTE4_07 : 24|8@1+ (1,0) [0|255] ""  PC
 SG_ S2P_DIAG_BYTE5_07 : 32|8@1+ (1,0) [0|255] ""  PC
 SG_ S2P_DIAG_BYTE6_07 : 40|8@1+ (1,0) [0|255] ""  PC
 SG_ S2P_DIAG_BYTE7_07 : 48|8@1+ (1,0) [0|255] ""  PC
 SG_ S2P_DIAG_BYTE8_07 : 56|8@1+ (1,0) [0|255] ""  PC

BO_ 2416045640 S2P_DIAG__08: 8 SBMU
 SG_ S2P_DIAG_BYTE1_08 : 0|8@1+ (1,0) [0|255] ""  PC
 SG_ S2P_DIAG_BYTE2_08 : 8|8@1+ (1,0) [0|255] ""  PC
 SG_ S2P_DIAG_BYTE3_08 : 16|8@1+ (1,0) [0|255] ""  PC
 SG_ S2P_DIAG_BYTE4_08 : 24|8@1+ (1,0) [0|255] ""  PC
 SG_ S2P_DIAG_BYTE5_08 : 32|8@1+ (1,0) [0|255] ""  PC
 SG_ S2P_DIAG_BYTE6_08 : 40|8@1+ (1,0) [0|255] ""  PC
 SG_ S2P_DIAG_BYTE7_08 : 48|8@1+ (1,0) [0|255] ""  PC
 SG_ S2P_DIAG_BYTE8_08 : 56|8@1+ (1,0) [0|255] ""  PC

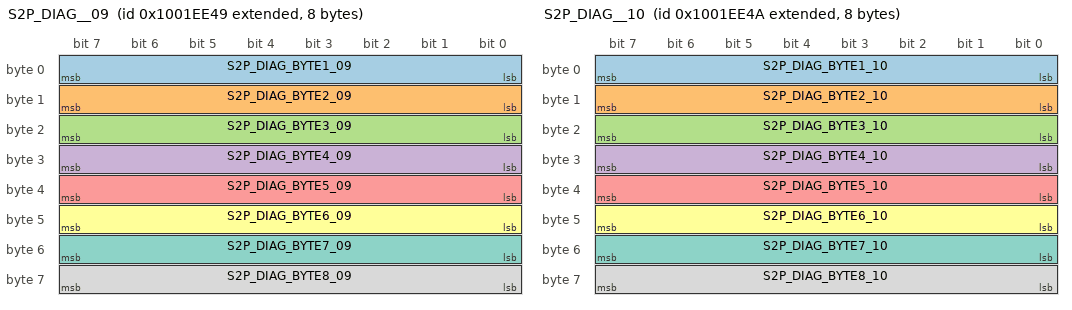
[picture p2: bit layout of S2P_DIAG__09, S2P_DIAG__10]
BO_ 2416045641 S2P_DIAG__09: 8 SBMU
 SG_ S2P_DIAG_BYTE1_09 : 0|8@1+ (1,0) [0|255] ""  PC
 SG_ S2P_DIAG_BYTE2_09 : 8|8@1+ (1,0) [0|255] ""  PC
 SG_ S2P_DIAG_BYTE3_09 : 16|8@1+ (1,0) [0|255] ""  PC
 SG_ S2P_DIAG_BYTE4_09 : 24|8@1+ (1,0) [0|255] ""  PC
 SG_ S2P_DIAG_BYTE5_09 : 32|8@1+ (1,0) [0|255] ""  PC
 SG_ S2P_DIAG_BYTE6_09 : 40|8@1+ (1,0) [0|255] ""  PC
 SG_ S2P_DIAG_BYTE7_09 : 48|8@1+ (1,0) [0|255] ""  PC
 SG_ S2P_DIAG_BYTE8_09 : 56|8@1+ (1,0) [0|255] ""  PC

BO_ 2416045642 S2P_DIAG__10: 8 SBMU
 SG_ S2P_DIAG_BYTE1_10 : 0|8@1+ (1,0) [0|255] ""  PC
 SG_ S2P_DIAG_BYTE2_10 : 8|8@1+ (1,0) [0|255] ""  PC
 SG_ S2P_DIAG_BYTE3_10 : 16|8@1+ (1,0) [0|255] ""  PC
 SG_ S2P_DIAG_BYTE4_10 : 24|8@1+ (1,0) [0|255] ""  PC
 SG_ S2P_DIAG_BYTE5_10 : 32|8@1+ (1,0) [0|255] ""  PC
 SG_ S2P_DIAG_BYTE6_10 : 40|8@1+ (1,0) [0|255] ""  PC
 SG_ S2P_DIAG_BYTE7_10 : 48|8@1+ (1,0) [0|255] ""  PC
 SG_ S2P_DIAG_BYTE8_10 : 56|8@1+ (1,0) [0|255] ""  PC

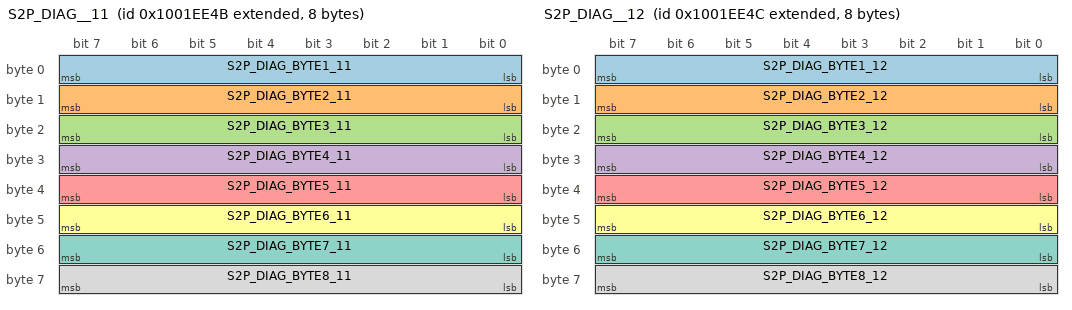
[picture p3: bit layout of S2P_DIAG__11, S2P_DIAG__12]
BO_ 2416045643 S2P_DIAG__11: 8 SBMU
 SG_ S2P_DIAG_BYTE1_11 : 0|8@1+ (1,0) [0|255] ""  PC
 SG_ S2P_DIAG_BYTE2_11 : 8|8@1+ (1,0) [0|255] ""  PC
 SG_ S2P_DIAG_BYTE3_11 : 16|8@1+ (1,0) [0|255] ""  PC
 SG_ S2P_DIAG_BYTE4_11 : 24|8@1+ (1,0) [0|255] ""  PC
 SG_ S2P_DIAG_BYTE5_11 : 32|8@1+ (1,0) [0|255] ""  PC
 SG_ S2P_DIAG_BYTE6_11 : 40|8@1+ (1,0) [0|255] ""  PC
 SG_ S2P_DIAG_BYTE7_11 : 48|8@1+ (1,0) [0|255] ""  PC
 SG_ S2P_DIAG_BYTE8_11 : 56|8@1+ (1,0) [0|255] ""  PC

BO_ 2416045644 S2P_DIAG__12: 8 SBMU
 SG_ S2P_DIAG_BYTE1_12 : 0|8@1+ (1,0) [0|255] ""  PC
 SG_ S2P_DIAG_BYTE2_12 : 8|8@1+ (1,0) [0|255] ""  PC
 SG_ S2P_DIAG_BYTE3_12 : 16|8@1+ (1,0) [0|255] ""  PC
 SG_ S2P_DIAG_BYTE4_12 : 24|8@1+ (1,0) [0|255] ""  PC
 SG_ S2P_DIAG_BYTE5_12 : 32|8@1+ (1,0) [0|255] ""  PC
 SG_ S2P_DIAG_BYTE6_12 : 40|8@1+ (1,0) [0|255] ""  PC
 SG_ S2P_DIAG_BYTE7_12 : 48|8@1+ (1,0) [0|255] ""  PC
 SG_ S2P_DIAG_BYTE8_12 : 56|8@1+ (1,0) [0|255] ""  PC

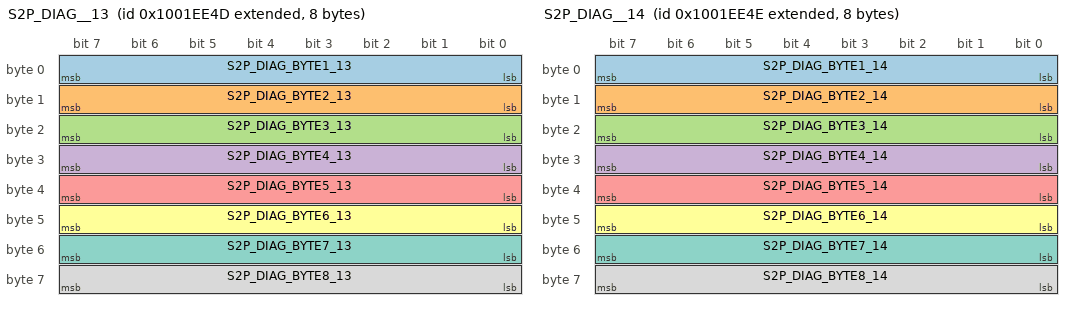
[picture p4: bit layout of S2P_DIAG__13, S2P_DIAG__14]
BO_ 2416045645 S2P_DIAG__13: 8 SBMU
 SG_ S2P_DIAG_BYTE1_13 : 0|8@1+ (1,0) [0|255] ""  PC
 SG_ S2P_DIAG_BYTE2_13 : 8|8@1+ (1,0) [0|255] ""  PC
 SG_ S2P_DIAG_BYTE3_13 : 16|8@1+ (1,0) [0|255] ""  PC
 SG_ S2P_DIAG_BYTE4_13 : 24|8@1+ (1,0) [0|255] ""  PC
 SG_ S2P_DIAG_BYTE5_13 : 32|8@1+ (1,0) [0|255] ""  PC
 SG_ S2P_DIAG_BYTE6_13 : 40|8@1+ (1,0) [0|255] ""  PC
 SG_ S2P_DIAG_BYTE7_13 : 48|8@1+ (1,0) [0|255] ""  PC
 SG_ S2P_DIAG_BYTE8_13 : 56|8@1+ (1,0) [0|255] ""  PC

BO_ 2416045646 S2P_DIAG__14: 8 SBMU
 SG_ S2P_DIAG_BYTE1_14 : 0|8@1+ (1,0) [0|255] ""  PC
 SG_ S2P_DIAG_BYTE2_14 : 8|8@1+ (1,0) [0|255] ""  PC
 SG_ S2P_DIAG_BYTE3_14 : 16|8@1+ (1,0) [0|255] ""  PC
 SG_ S2P_DIAG_BYTE4_14 : 24|8@1+ (1,0) [0|255] ""  PC
 SG_ S2P_DIAG_BYTE5_14 : 32|8@1+ (1,0) [0|255] ""  PC
 SG_ S2P_DIAG_BYTE6_14 : 40|8@1+ (1,0) [0|255] ""  PC
 SG_ S2P_DIAG_BYTE7_14 : 48|8@1+ (1,0) [0|255] ""  PC
 SG_ S2P_DIAG_BYTE8_14 : 56|8@1+ (1,0) [0|255] ""  PC

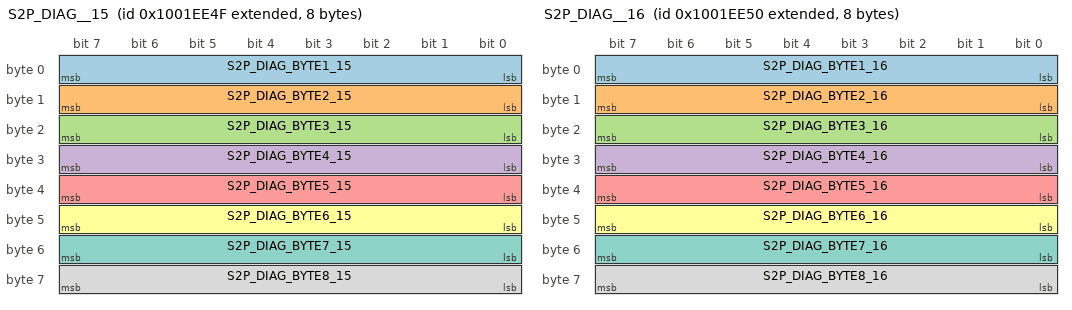
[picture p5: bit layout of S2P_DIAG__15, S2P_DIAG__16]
BO_ 2416045647 S2P_DIAG__15: 8 SBMU
 SG_ S2P_DIAG_BYTE1_15 : 0|8@1+ (1,0) [0|255] ""  PC
 SG_ S2P_DIAG_BYTE2_15 : 8|8@1+ (1,0) [0|255] ""  PC
 SG_ S2P_DIAG_BYTE3_15 : 16|8@1+ (1,0) [0|255] ""  PC
 SG_ S2P_DIAG_BYTE4_15 : 24|8@1+ (1,0) [0|255] ""  PC
 SG_ S2P_DIAG_BYTE5_15 : 32|8@1+ (1,0) [0|255] ""  PC
 SG_ S2P_DIAG_BYTE6_15 : 40|8@1+ (1,0) [0|255] ""  PC
 SG_ S2P_DIAG_BYTE7_15 : 48|8@1+ (1,0) [0|255] ""  PC
 SG_ S2P_DIAG_BYTE8_15 : 56|8@1+ (1,0) [0|255] ""  PC

BO_ 2416045648 S2P_DIAG__16: 8 SBMU
 SG_ S2P_DIAG_BYTE1_16 : 0|8@1+ (1,0) [0|255] ""  PC
 SG_ S2P_DIAG_BYTE2_16 : 8|8@1+ (1,0) [0|255] ""  PC
 SG_ S2P_DIAG_BYTE3_16 : 16|8@1+ (1,0) [0|255] ""  PC
 SG_ S2P_DIAG_BYTE4_16 : 24|8@1+ (1,0) [0|255] ""  PC
 SG_ S2P_DIAG_BYTE5_16 : 32|8@1+ (1,0) [0|255] ""  PC
 SG_ S2P_DIAG_BYTE6_16 : 40|8@1+ (1,0) [0|255] ""  PC
 SG_ S2P_DIAG_BYTE7_16 : 48|8@1+ (1,0) [0|255] ""  PC
 SG_ S2P_DIAG_BYTE8_16 : 56|8@1+ (1,0) [0|255] ""  PC

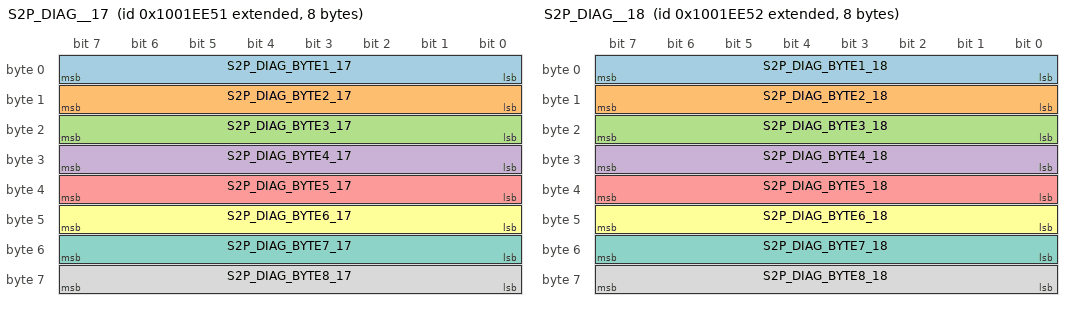
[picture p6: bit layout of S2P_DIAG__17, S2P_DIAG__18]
BO_ 2416045649 S2P_DIAG__17: 8 SBMU
 SG_ S2P_DIAG_BYTE1_17 : 0|8@1+ (1,0) [0|255] ""  PC
 SG_ S2P_DIAG_BYTE2_17 : 8|8@1+ (1,0) [0|255] ""  PC
 SG_ S2P_DIAG_BYTE3_17 : 16|8@1+ (1,0) [0|255] ""  PC
 SG_ S2P_DIAG_BYTE4_17 : 24|8@1+ (1,0) [0|255] ""  PC
 SG_ S2P_DIAG_BYTE5_17 : 32|8@1+ (1,0) [0|255] ""  PC
 SG_ S2P_DIAG_BYTE6_17 : 40|8@1+ (1,0) [0|255] ""  PC
 SG_ S2P_DIAG_BYTE7_17 : 48|8@1+ (1,0) [0|255] ""  PC
 SG_ S2P_DIAG_BYTE8_17 : 56|8@1+ (1,0) [0|255] ""  PC

BO_ 2416045650 S2P_DIAG__18: 8 SBMU
 SG_ S2P_DIAG_BYTE1_18 : 0|8@1+ (1,0) [0|255] ""  PC
 SG_ S2P_DIAG_BYTE2_18 : 8|8@1+ (1,0) [0|255] ""  PC
 SG_ S2P_DIAG_BYTE3_18 : 16|8@1+ (1,0) [0|255] ""  PC
 SG_ S2P_DIAG_BYTE4_18 : 24|8@1+ (1,0) [0|255] ""  PC
 SG_ S2P_DIAG_BYTE5_18 : 32|8@1+ (1,0) [0|255] ""  PC
 SG_ S2P_DIAG_BYTE6_18 : 40|8@1+ (1,0) [0|255] ""  PC
 SG_ S2P_DIAG_BYTE7_18 : 48|8@1+ (1,0) [0|255] ""  PC
 SG_ S2P_DIAG_BYTE8_18 : 56|8@1+ (1,0) [0|255] ""  PC

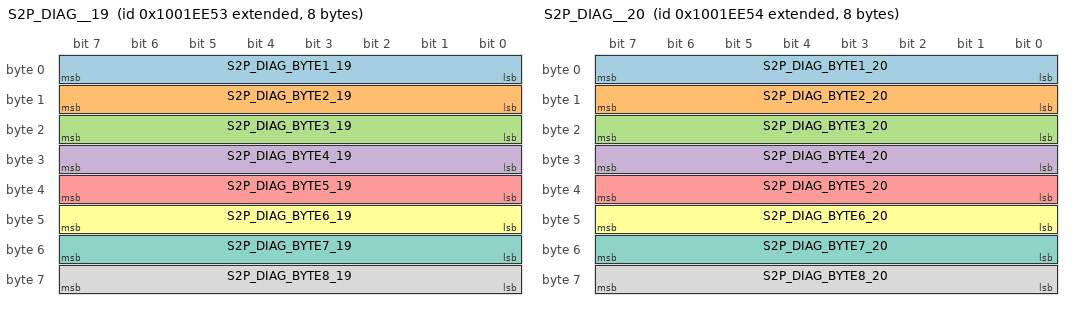
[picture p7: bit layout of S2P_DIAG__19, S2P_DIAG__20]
BO_ 2416045651 S2P_DIAG__19: 8 SBMU
 SG_ S2P_DIAG_BYTE1_19 : 0|8@1+ (1,0) [0|255] ""  PC
 SG_ S2P_DIAG_BYTE2_19 : 8|8@1+ (1,0) [0|255] ""  PC
 SG_ S2P_DIAG_BYTE3_19 : 16|8@1+ (1,0) [0|255] ""  PC
 SG_ S2P_DIAG_BYTE4_19 : 24|8@1+ (1,0) [0|255] ""  PC
 SG_ S2P_DIAG_BYTE5_19 : 32|8@1+ (1,0) [0|255] ""  PC
 SG_ S2P_DIAG_BYTE6_19 : 40|8@1+ (1,0) [0|255] ""  PC
 SG_ S2P_DIAG_BYTE7_19 : 48|8@1+ (1,0) [0|255] ""  PC
 SG_ S2P_DIAG_BYTE8_19 : 56|8@1+ (1,0) [0|255] ""  PC

BO_ 2416045652 S2P_DIAG__20: 8 SBMU
 SG_ S2P_DIAG_BYTE1_20 : 0|8@1+ (1,0) [0|255] ""  PC
 SG_ S2P_DIAG_BYTE2_20 : 8|8@1+ (1,0) [0|255] ""  PC
 SG_ S2P_DIAG_BYTE3_20 : 16|8@1+ (1,0) [0|255] ""  PC
 SG_ S2P_DIAG_BYTE4_20 : 24|8@1+ (1,0) [0|255] ""  PC
 SG_ S2P_DIAG_BYTE5_20 : 32|8@1+ (1,0) [0|255] ""  PC
 SG_ S2P_DIAG_BYTE6_20 : 40|8@1+ (1,0) [0|255] ""  PC
 SG_ S2P_DIAG_BYTE7_20 : 48|8@1+ (1,0) [0|255] ""  PC
 SG_ S2P_DIAG_BYTE8_20 : 56|8@1+ (1,0) [0|255] ""  PC

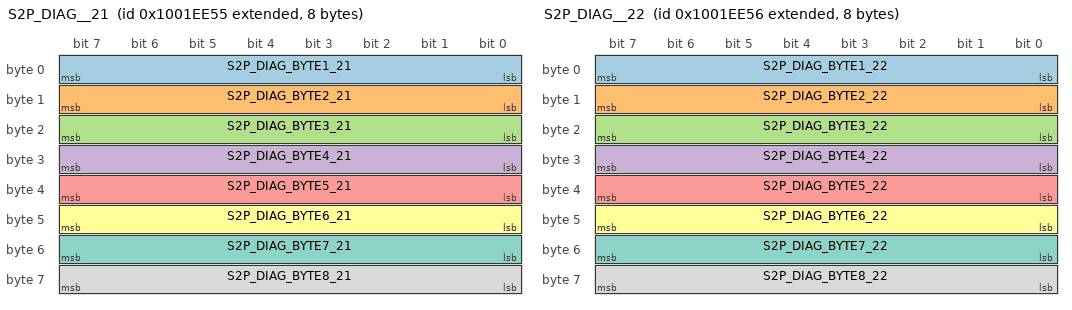
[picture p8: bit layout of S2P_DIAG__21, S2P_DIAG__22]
BO_ 2416045653 S2P_DIAG__21: 8 SBMU
 SG_ S2P_DIAG_BYTE1_21 : 0|8@1+ (1,0) [0|255] ""  PC
 SG_ S2P_DIAG_BYTE2_21 : 8|8@1+ (1,0) [0|255] ""  PC
 SG_ S2P_DIAG_BYTE3_21 : 16|8@1+ (1,0) [0|255] ""  PC
 SG_ S2P_DIAG_BYTE4_21 : 24|8@1+ (1,0) [0|255] ""  PC
 SG_ S2P_DIAG_BYTE5_21 : 32|8@1+ (1,0) [0|255] ""  PC
 SG_ S2P_DIAG_BYTE6_21 : 40|8@1+ (1,0) [0|255] ""  PC
 SG_ S2P_DIAG_BYTE7_21 : 48|8@1+ (1,0) [0|255] ""  PC
 SG_ S2P_DIAG_BYTE8_21 : 56|8@1+ (1,0) [0|255] ""  PC

BO_ 2416045654 S2P_DIAG__22: 8 SBMU
 SG_ S2P_DIAG_BYTE1_22 : 0|8@1+ (1,0) [0|255] ""  PC
 SG_ S2P_DIAG_BYTE2_22 : 8|8@1+ (1,0) [0|255] ""  PC
 SG_ S2P_DIAG_BYTE3_22 : 16|8@1+ (1,0) [0|255] ""  PC
 SG_ S2P_DIAG_BYTE4_22 : 24|8@1+ (1,0) [0|255] ""  PC
 SG_ S2P_DIAG_BYTE5_22 : 32|8@1+ (1,0) [0|255] ""  PC
 SG_ S2P_DIAG_BYTE6_22 : 40|8@1+ (1,0) [0|255] ""  PC
 SG_ S2P_DIAG_BYTE7_22 : 48|8@1+ (1,0) [0|255] ""  PC
 SG_ S2P_DIAG_BYTE8_22 : 56|8@1+ (1,0) [0|255] ""  PC

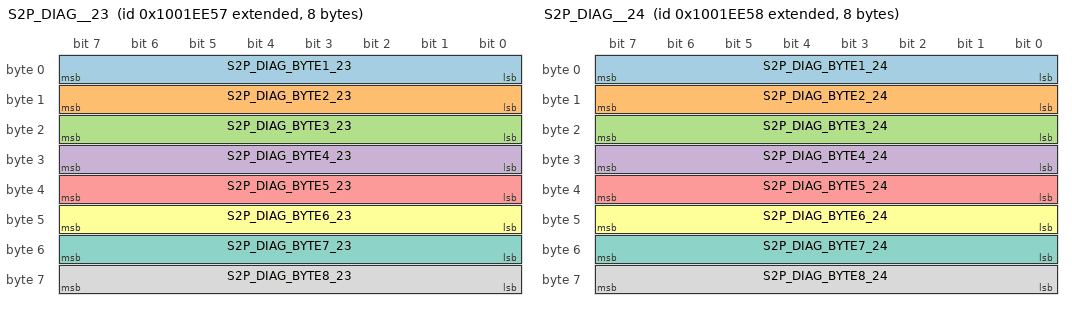
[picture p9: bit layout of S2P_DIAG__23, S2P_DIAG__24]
BO_ 2416045655 S2P_DIAG__23: 8 SBMU
 SG_ S2P_DIAG_BYTE1_23 : 0|8@1+ (1,0) [0|255] ""  PC
 SG_ S2P_DIAG_BYTE2_23 : 8|8@1+ (1,0) [0|255] ""  PC
 SG_ S2P_DIAG_BYTE3_23 : 16|8@1+ (1,0) [0|255] ""  PC
 SG_ S2P_DIAG_BYTE4_23 : 24|8@1+ (1,0) [0|255] ""  PC
 SG_ S2P_DIAG_BYTE5_23 : 32|8@1+ (1,0) [0|255] ""  PC
 SG_ S2P_DIAG_BYTE6_23 : 40|8@1+ (1,0) [0|255] ""  PC
 SG_ S2P_DIAG_BYTE7_23 : 48|8@1+ (1,0) [0|255] ""  PC
 SG_ S2P_DIAG_BYTE8_23 : 56|8@1+ (1,0) [0|255] ""  PC

BO_ 2416045656 S2P_DIAG__24: 8 SBMU
 SG_ S2P_DIAG_BYTE1_24 : 0|8@1+ (1,0) [0|255] ""  PC
 SG_ S2P_DIAG_BYTE2_24 : 8|8@1+ (1,0) [0|255] ""  PC
 SG_ S2P_DIAG_BYTE3_24 : 16|8@1+ (1,0) [0|255] ""  PC
 SG_ S2P_DIAG_BYTE4_24 : 24|8@1+ (1,0) [0|255] ""  PC
 SG_ S2P_DIAG_BYTE5_24 : 32|8@1+ (1,0) [0|255] ""  PC
 SG_ S2P_DIAG_BYTE6_24 : 40|8@1+ (1,0) [0|255] ""  PC
 SG_ S2P_DIAG_BYTE7_24 : 48|8@1+ (1,0) [0|255] ""  PC
 SG_ S2P_DIAG_BYTE8_24 : 56|8@1+ (1,0) [0|255] ""  PC

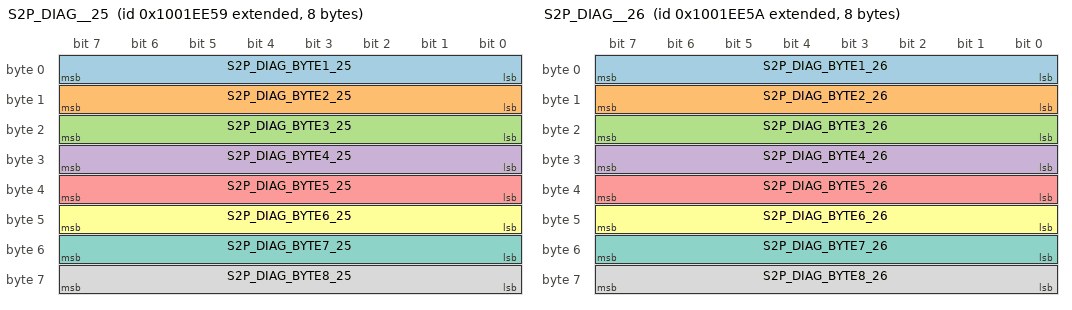
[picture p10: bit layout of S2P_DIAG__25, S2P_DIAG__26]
BO_ 2416045657 S2P_DIAG__25: 8 SBMU
 SG_ S2P_DIAG_BYTE1_25 : 0|8@1+ (1,0) [0|255] ""  PC
 SG_ S2P_DIAG_BYTE2_25 : 8|8@1+ (1,0) [0|255] ""  PC
 SG_ S2P_DIAG_BYTE3_25 : 16|8@1+ (1,0) [0|255] ""  PC
 SG_ S2P_DIAG_BYTE4_25 : 24|8@1+ (1,0) [0|255] ""  PC
 SG_ S2P_DIAG_BYTE5_25 : 32|8@1+ (1,0) [0|255] ""  PC
 SG_ S2P_DIAG_BYTE6_25 : 40|8@1+ (1,0) [0|255] ""  PC
 SG_ S2P_DIAG_BYTE7_25 : 48|8@1+ (1,0) [0|255] ""  PC
 SG_ S2P_DIAG_BYTE8_25 : 56|8@1+ (1,0) [0|255] ""  PC

BO_ 2416045658 S2P_DIAG__26: 8 SBMU
 SG_ S2P_DIAG_BYTE1_26 : 0|8@1+ (1,0) [0|255] ""  PC
 SG_ S2P_DIAG_BYTE2_26 : 8|8@1+ (1,0) [0|255] ""  PC
 SG_ S2P_DIAG_BYTE3_26 : 16|8@1+ (1,0) [0|255] ""  PC
 SG_ S2P_DIAG_BYTE4_26 : 24|8@1+ (1,0) [0|255] ""  PC
 SG_ S2P_DIAG_BYTE5_26 : 32|8@1+ (1,0) [0|255] ""  PC
 SG_ S2P_DIAG_BYTE6_26 : 40|8@1+ (1,0) [0|255] ""  PC
 SG_ S2P_DIAG_BYTE7_26 : 48|8@1+ (1,0) [0|255] ""  PC
 SG_ S2P_DIAG_BYTE8_26 : 56|8@1+ (1,0) [0|255] ""  PC

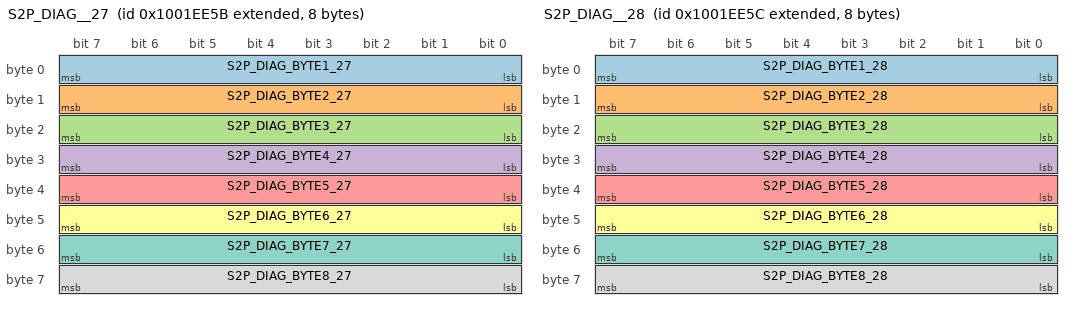
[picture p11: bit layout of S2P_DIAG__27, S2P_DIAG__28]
BO_ 2416045659 S2P_DIAG__27: 8 SBMU
 SG_ S2P_DIAG_BYTE1_27 : 0|8@1+ (1,0) [0|255] ""  PC
 SG_ S2P_DIAG_BYTE2_27 : 8|8@1+ (1,0) [0|255] ""  PC
 SG_ S2P_DIAG_BYTE3_27 : 16|8@1+ (1,0) [0|255] ""  PC
 SG_ S2P_DIAG_BYTE4_27 : 24|8@1+ (1,0) [0|255] ""  PC
 SG_ S2P_DIAG_BYTE5_27 : 32|8@1+ (1,0) [0|255] ""  PC
 SG_ S2P_DIAG_BYTE6_27 : 40|8@1+ (1,0) [0|255] ""  PC
 SG_ S2P_DIAG_BYTE7_27 : 48|8@1+ (1,0) [0|255] ""  PC
 SG_ S2P_DIAG_BYTE8_27 : 56|8@1+ (1,0) [0|255] ""  PC

BO_ 2416045660 S2P_DIAG__28: 8 SBMU
 SG_ S2P_DIAG_BYTE1_28 : 0|8@1+ (1,0) [0|255] ""  PC
 SG_ S2P_DIAG_BYTE2_28 : 8|8@1+ (1,0) [0|255] ""  PC
 SG_ S2P_DIAG_BYTE3_28 : 16|8@1+ (1,0) [0|255] ""  PC
 SG_ S2P_DIAG_BYTE4_28 : 24|8@1+ (1,0) [0|255] ""  PC
 SG_ S2P_DIAG_BYTE5_28 : 32|8@1+ (1,0) [0|255] ""  PC
 SG_ S2P_DIAG_BYTE6_28 : 40|8@1+ (1,0) [0|255] ""  PC
 SG_ S2P_DIAG_BYTE7_28 : 48|8@1+ (1,0) [0|255] ""  PC
 SG_ S2P_DIAG_BYTE8_28 : 56|8@1+ (1,0) [0|255] ""  PC

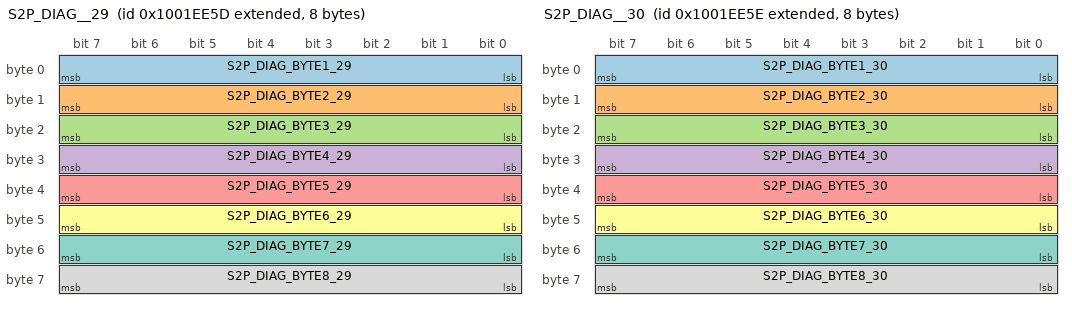
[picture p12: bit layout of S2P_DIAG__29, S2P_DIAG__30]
BO_ 2416045661 S2P_DIAG__29: 8 SBMU
 SG_ S2P_DIAG_BYTE1_29 : 0|8@1+ (1,0) [0|255] ""  PC
 SG_ S2P_DIAG_BYTE2_29 : 8|8@1+ (1,0) [0|255] ""  PC
 SG_ S2P_DIAG_BYTE3_29 : 16|8@1+ (1,0) [0|255] ""  PC
 SG_ S2P_DIAG_BYTE4_29 : 24|8@1+ (1,0) [0|255] ""  PC
 SG_ S2P_DIAG_BYTE5_29 : 32|8@1+ (1,0) [0|255] ""  PC
 SG_ S2P_DIAG_BYTE6_29 : 40|8@1+ (1,0) [0|255] ""  PC
 SG_ S2P_DIAG_BYTE7_29 : 48|8@1+ (1,0) [0|255] ""  PC
 SG_ S2P_DIAG_BYTE8_29 : 56|8@1+ (1,0) [0|255] ""  PC

BO_ 2416045662 S2P_DIAG__30: 8 SBMU
 SG_ S2P_DIAG_BYTE1_30 : 0|8@1+ (1,0) [0|255] ""  PC
 SG_ S2P_DIAG_BYTE2_30 : 8|8@1+ (1,0) [0|255] ""  PC
 SG_ S2P_DIAG_BYTE3_30 : 16|8@1+ (1,0) [0|255] ""  PC
 SG_ S2P_DIAG_BYTE4_30 : 24|8@1+ (1,0) [0|255] ""  PC
 SG_ S2P_DIAG_BYTE5_30 : 32|8@1+ (1,0) [0|255] ""  PC
 SG_ S2P_DIAG_BYTE6_30 : 40|8@1+ (1,0) [0|255] ""  PC
 SG_ S2P_DIAG_BYTE7_30 : 48|8@1+ (1,0) [0|255] ""  PC
 SG_ S2P_DIAG_BYTE8_30 : 56|8@1+ (1,0) [0|255] ""  PC

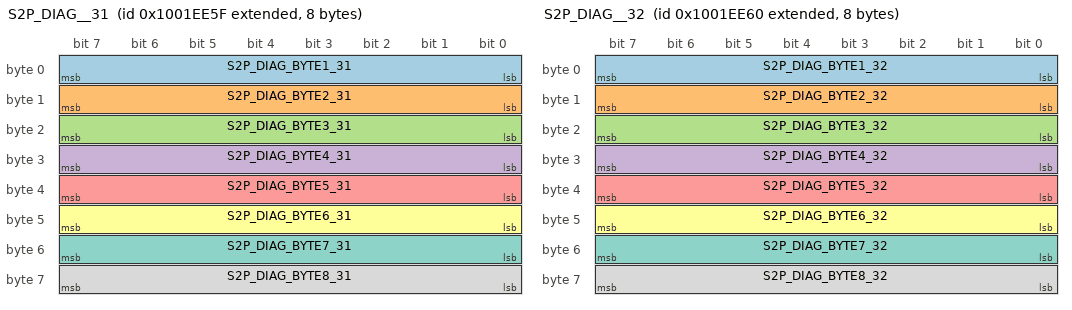
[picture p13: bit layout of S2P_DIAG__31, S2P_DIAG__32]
BO_ 2416045663 S2P_DIAG__31: 8 SBMU
 SG_ S2P_DIAG_BYTE1_31 : 0|8@1+ (1,0) [0|255] ""  PC
 SG_ S2P_DIAG_BYTE2_31 : 8|8@1+ (1,0) [0|255] ""  PC
 SG_ S2P_DIAG_BYTE3_31 : 16|8@1+ (1,0) [0|255] ""  PC
 SG_ S2P_DIAG_BYTE4_31 : 24|8@1+ (1,0) [0|255] ""  PC
 SG_ S2P_DIAG_BYTE5_31 : 32|8@1+ (1,0) [0|255] ""  PC
 SG_ S2P_DIAG_BYTE6_31 : 40|8@1+ (1,0) [0|255] ""  PC
 SG_ S2P_DIAG_BYTE7_31 : 48|8@1+ (1,0) [0|255] ""  PC
 SG_ S2P_DIAG_BYTE8_31 : 56|8@1+ (1,0) [0|255] ""  PC

BO_ 2416045664 S2P_DIAG__32: 8 SBMU
 SG_ S2P_DIAG_BYTE1_32 : 0|8@1+ (1,0) [0|255] ""  PC
 SG_ S2P_DIAG_BYTE2_32 : 8|8@1+ (1,0) [0|255] ""  PC
 SG_ S2P_DIAG_BYTE3_32 : 16|8@1+ (1,0) [0|255] ""  PC
 SG_ S2P_DIAG_BYTE4_32 : 24|8@1+ (1,0) [0|255] ""  PC
 SG_ S2P_DIAG_BYTE5_32 : 32|8@1+ (1,0) [0|255] ""  PC
 SG_ S2P_DIAG_BYTE6_32 : 40|8@1+ (1,0) [0|255] ""  PC
 SG_ S2P_DIAG_BYTE7_32 : 48|8@1+ (1,0) [0|255] ""  PC
 SG_ S2P_DIAG_BYTE8_32 : 56|8@1+ (1,0) [0|255] ""  PC

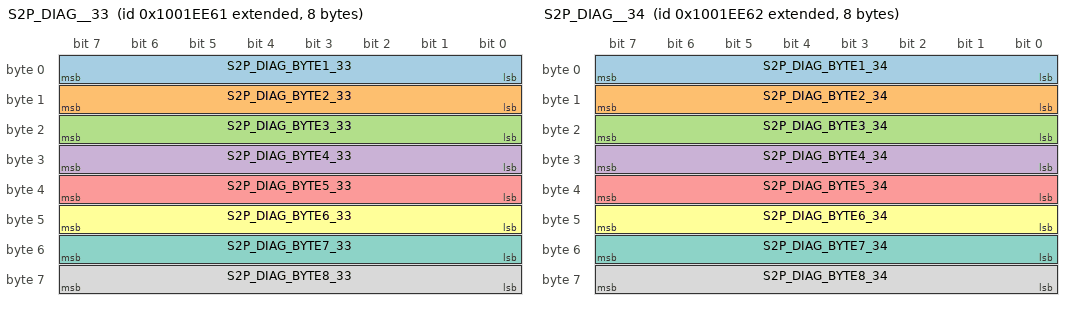
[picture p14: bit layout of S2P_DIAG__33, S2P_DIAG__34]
BO_ 2416045665 S2P_DIAG__33: 8 SBMU
 SG_ S2P_DIAG_BYTE1_33 : 0|8@1+ (1,0) [0|255] ""  PC
 SG_ S2P_DIAG_BYTE2_33 : 8|8@1+ (1,0) [0|255] ""  PC
 SG_ S2P_DIAG_BYTE3_33 : 16|8@1+ (1,0) [0|255] ""  PC
 SG_ S2P_DIAG_BYTE4_33 : 24|8@1+ (1,0) [0|255] ""  PC
 SG_ S2P_DIAG_BYTE5_33 : 32|8@1+ (1,0) [0|255] ""  PC
 SG_ S2P_DIAG_BYTE6_33 : 40|8@1+ (1,0) [0|255] ""  PC
 SG_ S2P_DIAG_BYTE7_33 : 48|8@1+ (1,0) [0|255] ""  PC
 SG_ S2P_DIAG_BYTE8_33 : 56|8@1+ (1,0) [0|255] ""  PC

BO_ 2416045666 S2P_DIAG__34: 8 SBMU
 SG_ S2P_DIAG_BYTE1_34 : 0|8@1+ (1,0) [0|255] ""  PC
 SG_ S2P_DIAG_BYTE2_34 : 8|8@1+ (1,0) [0|255] ""  PC
 SG_ S2P_DIAG_BYTE3_34 : 16|8@1+ (1,0) [0|255] ""  PC
 SG_ S2P_DIAG_BYTE4_34 : 24|8@1+ (1,0) [0|255] ""  PC
 SG_ S2P_DIAG_BYTE5_34 : 32|8@1+ (1,0) [0|255] ""  PC
 SG_ S2P_DIAG_BYTE6_34 : 40|8@1+ (1,0) [0|255] ""  PC
 SG_ S2P_DIAG_BYTE7_34 : 48|8@1+ (1,0) [0|255] ""  PC
 SG_ S2P_DIAG_BYTE8_34 : 56|8@1+ (1,0) [0|255] ""  PC

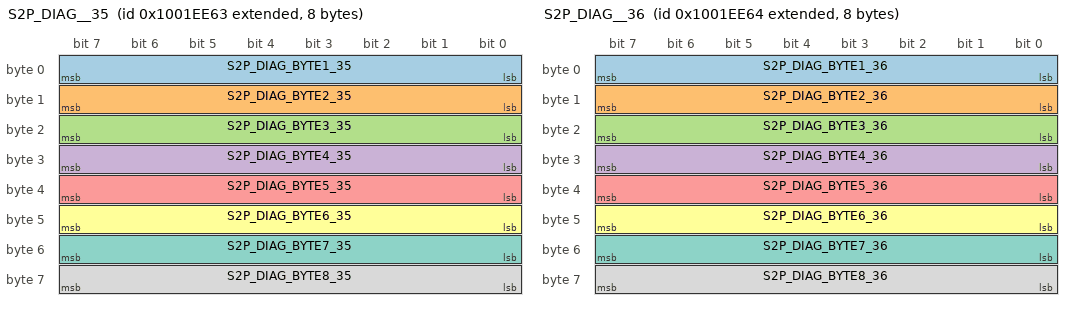
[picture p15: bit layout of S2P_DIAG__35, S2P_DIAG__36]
BO_ 2416045667 S2P_DIAG__35: 8 SBMU
 SG_ S2P_DIAG_BYTE1_35 : 0|8@1+ (1,0) [0|255] ""  PC
 SG_ S2P_DIAG_BYTE2_35 : 8|8@1+ (1,0) [0|255] ""  PC
 SG_ S2P_DIAG_BYTE3_35 : 16|8@1+ (1,0) [0|255] ""  PC
 SG_ S2P_DIAG_BYTE4_35 : 24|8@1+ (1,0) [0|255] ""  PC
 SG_ S2P_DIAG_BYTE5_35 : 32|8@1+ (1,0) [0|255] ""  PC
 SG_ S2P_DIAG_BYTE6_35 : 40|8@1+ (1,0) [0|255] ""  PC
 SG_ S2P_DIAG_BYTE7_35 : 48|8@1+ (1,0) [0|255] ""  PC
 SG_ S2P_DIAG_BYTE8_35 : 56|8@1+ (1,0) [0|255] ""  PC

BO_ 2416045668 S2P_DIAG__36: 8 SBMU
 SG_ S2P_DIAG_BYTE1_36 : 0|8@1+ (1,0) [0|255] ""  PC
 SG_ S2P_DIAG_BYTE2_36 : 8|8@1+ (1,0) [0|255] ""  PC
 SG_ S2P_DIAG_BYTE3_36 : 16|8@1+ (1,0) [0|255] ""  PC
 SG_ S2P_DIAG_BYTE4_36 : 24|8@1+ (1,0) [0|255] ""  PC
 SG_ S2P_DIAG_BYTE5_36 : 32|8@1+ (1,0) [0|255] ""  PC
 SG_ S2P_DIAG_BYTE6_36 : 40|8@1+ (1,0) [0|255] ""  PC
 SG_ S2P_DIAG_BYTE7_36 : 48|8@1+ (1,0) [0|255] ""  PC
 SG_ S2P_DIAG_BYTE8_36 : 56|8@1+ (1,0) [0|255] ""  PC

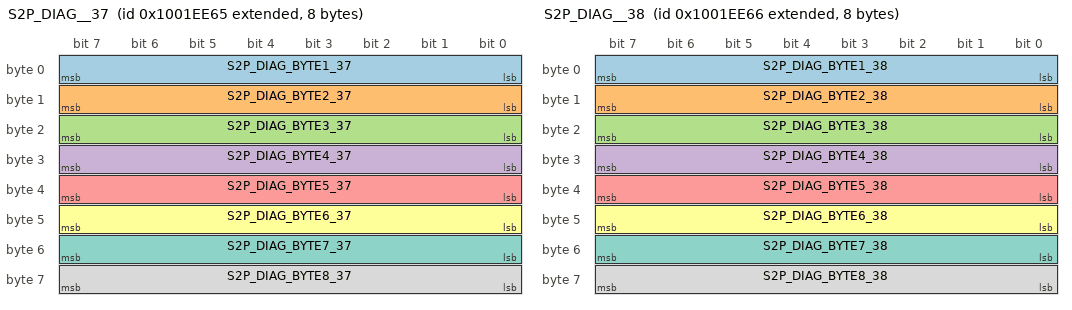
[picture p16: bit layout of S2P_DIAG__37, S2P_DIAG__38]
BO_ 2416045669 S2P_DIAG__37: 8 SBMU
 SG_ S2P_DIAG_BYTE1_37 : 0|8@1+ (1,0) [0|255] ""  PC
 SG_ S2P_DIAG_BYTE2_37 : 8|8@1+ (1,0) [0|255] ""  PC
 SG_ S2P_DIAG_BYTE3_37 : 16|8@1+ (1,0) [0|255] ""  PC
 SG_ S2P_DIAG_BYTE4_37 : 24|8@1+ (1,0) [0|255] ""  PC
 SG_ S2P_DIAG_BYTE5_37 : 32|8@1+ (1,0) [0|255] ""  PC
 SG_ S2P_DIAG_BYTE6_37 : 40|8@1+ (1,0) [0|255] ""  PC
 SG_ S2P_DIAG_BYTE7_37 : 48|8@1+ (1,0) [0|255] ""  PC
 SG_ S2P_DIAG_BYTE8_37 : 56|8@1+ (1,0) [0|255] ""  PC

BO_ 2416045670 S2P_DIAG__38: 8 SBMU
 SG_ S2P_DIAG_BYTE1_38 : 0|8@1+ (1,0) [0|255] ""  PC
 SG_ S2P_DIAG_BYTE2_38 : 8|8@1+ (1,0) [0|255] ""  PC
 SG_ S2P_DIAG_BYTE3_38 : 16|8@1+ (1,0) [0|255] ""  PC
 SG_ S2P_DIAG_BYTE4_38 : 24|8@1+ (1,0) [0|255] ""  PC
 SG_ S2P_DIAG_BYTE5_38 : 32|8@1+ (1,0) [0|255] ""  PC
 SG_ S2P_DIAG_BYTE6_38 : 40|8@1+ (1,0) [0|255] ""  PC
 SG_ S2P_DIAG_BYTE7_38 : 48|8@1+ (1,0) [0|255] ""  PC
 SG_ S2P_DIAG_BYTE8_38 : 56|8@1+ (1,0) [0|255] ""  PC

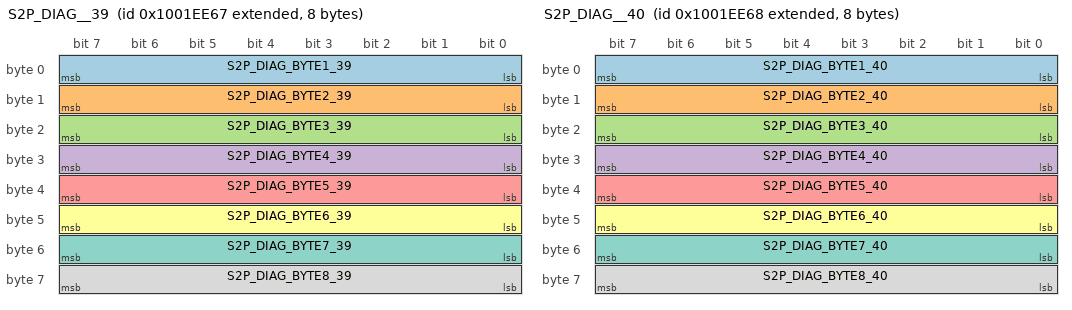
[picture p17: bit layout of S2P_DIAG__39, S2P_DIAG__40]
BO_ 2416045671 S2P_DIAG__39: 8 SBMU
 SG_ S2P_DIAG_BYTE1_39 : 0|8@1+ (1,0) [0|255] ""  PC
 SG_ S2P_DIAG_BYTE2_39 : 8|8@1+ (1,0) [0|255] ""  PC
 SG_ S2P_DIAG_BYTE3_39 : 16|8@1+ (1,0) [0|255] ""  PC
 SG_ S2P_DIAG_BYTE4_39 : 24|8@1+ (1,0) [0|255] ""  PC
 SG_ S2P_DIAG_BYTE5_39 : 32|8@1+ (1,0) [0|255] ""  PC
 SG_ S2P_DIAG_BYTE6_39 : 40|8@1+ (1,0) [0|255] ""  PC
 SG_ S2P_DIAG_BYTE7_39 : 48|8@1+ (1,0) [0|255] ""  PC
 SG_ S2P_DIAG_BYTE8_39 : 56|8@1+ (1,0) [0|255] ""  PC

BO_ 2416045672 S2P_DIAG__40: 8 SBMU
 SG_ S2P_DIAG_BYTE1_40 : 0|8@1+ (1,0) [0|255] ""  PC
 SG_ S2P_DIAG_BYTE2_40 : 8|8@1+ (1,0) [0|255] ""  PC
 SG_ S2P_DIAG_BYTE3_40 : 16|8@1+ (1,0) [0|255] ""  PC
 SG_ S2P_DIAG_BYTE4_40 : 24|8@1+ (1,0) [0|255] ""  PC
 SG_ S2P_DIAG_BYTE5_40 : 32|8@1+ (1,0) [0|255] ""  PC
 SG_ S2P_DIAG_BYTE6_40 : 40|8@1+ (1,0) [0|255] ""  PC
 SG_ S2P_DIAG_BYTE7_40 : 48|8@1+ (1,0) [0|255] ""  PC
 SG_ S2P_DIAG_BYTE8_40 : 56|8@1+ (1,0) [0|255] ""  PC

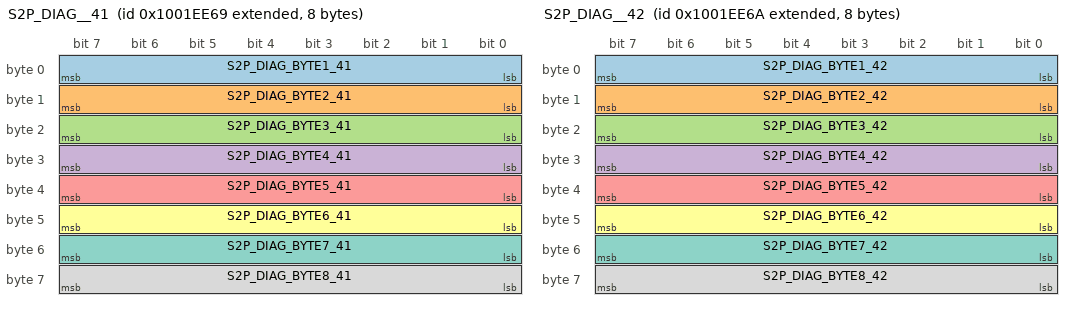
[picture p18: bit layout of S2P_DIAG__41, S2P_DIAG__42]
BO_ 2416045673 S2P_DIAG__41: 8 SBMU
 SG_ S2P_DIAG_BYTE1_41 : 0|8@1+ (1,0) [0|255] ""  PC
 SG_ S2P_DIAG_BYTE2_41 : 8|8@1+ (1,0) [0|255] ""  PC
 SG_ S2P_DIAG_BYTE3_41 : 16|8@1+ (1,0) [0|255] ""  PC
 SG_ S2P_DIAG_BYTE4_41 : 24|8@1+ (1,0) [0|255] ""  PC
 SG_ S2P_DIAG_BYTE5_41 : 32|8@1+ (1,0) [0|255] ""  PC
 SG_ S2P_DIAG_BYTE6_41 : 40|8@1+ (1,0) [0|255] ""  PC
 SG_ S2P_DIAG_BYTE7_41 : 48|8@1+ (1,0) [0|255] ""  PC
 SG_ S2P_DIAG_BYTE8_41 : 56|8@1+ (1,0) [0|255] ""  PC

BO_ 2416045674 S2P_DIAG__42: 8 SBMU
 SG_ S2P_DIAG_BYTE1_42 : 0|8@1+ (1,0) [0|255] ""  PC
 SG_ S2P_DIAG_BYTE2_42 : 8|8@1+ (1,0) [0|255] ""  PC
 SG_ S2P_DIAG_BYTE3_42 : 16|8@1+ (1,0) [0|255] ""  PC
 SG_ S2P_DIAG_BYTE4_42 : 24|8@1+ (1,0) [0|255] ""  PC
 SG_ S2P_DIAG_BYTE5_42 : 32|8@1+ (1,0) [0|255] ""  PC
 SG_ S2P_DIAG_BYTE6_42 : 40|8@1+ (1,0) [0|255] ""  PC
 SG_ S2P_DIAG_BYTE7_42 : 48|8@1+ (1,0) [0|255] ""  PC
 SG_ S2P_DIAG_BYTE8_42 : 56|8@1+ (1,0) [0|255] ""  PC

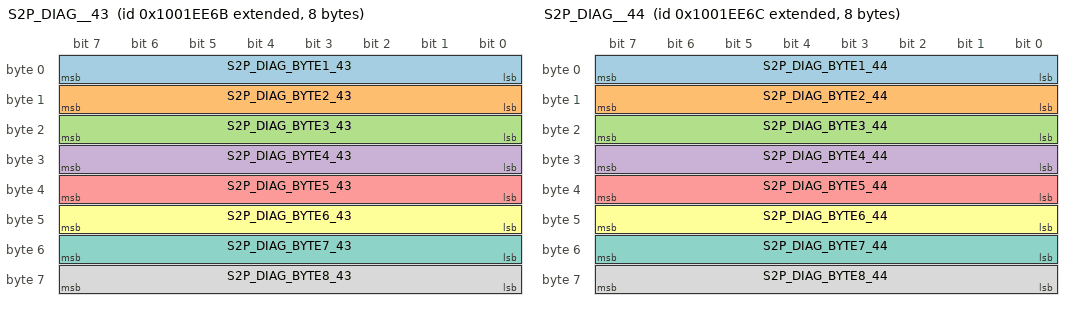
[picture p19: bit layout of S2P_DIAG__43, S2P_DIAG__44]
BO_ 2416045675 S2P_DIAG__43: 8 SBMU
 SG_ S2P_DIAG_BYTE1_43 : 0|8@1+ (1,0) [0|255] ""  PC
 SG_ S2P_DIAG_BYTE2_43 : 8|8@1+ (1,0) [0|255] ""  PC
 SG_ S2P_DIAG_BYTE3_43 : 16|8@1+ (1,0) [0|255] ""  PC
 SG_ S2P_DIAG_BYTE4_43 : 24|8@1+ (1,0) [0|255] ""  PC
 SG_ S2P_DIAG_BYTE5_43 : 32|8@1+ (1,0) [0|255] ""  PC
 SG_ S2P_DIAG_BYTE6_43 : 40|8@1+ (1,0) [0|255] ""  PC
 SG_ S2P_DIAG_BYTE7_43 : 48|8@1+ (1,0) [0|255] ""  PC
 SG_ S2P_DIAG_BYTE8_43 : 56|8@1+ (1,0) [0|255] ""  PC

BO_ 2416045676 S2P_DIAG__44: 8 SBMU
 SG_ S2P_DIAG_BYTE1_44 : 0|8@1+ (1,0) [0|255] ""  PC
 SG_ S2P_DIAG_BYTE2_44 : 8|8@1+ (1,0) [0|255] ""  PC
 SG_ S2P_DIAG_BYTE3_44 : 16|8@1+ (1,0) [0|255] ""  PC
 SG_ S2P_DIAG_BYTE4_44 : 24|8@1+ (1,0) [0|255] ""  PC
 SG_ S2P_DIAG_BYTE5_44 : 32|8@1+ (1,0) [0|255] ""  PC
 SG_ S2P_DIAG_BYTE6_44 : 40|8@1+ (1,0) [0|255] ""  PC
 SG_ S2P_DIAG_BYTE7_44 : 48|8@1+ (1,0) [0|255] ""  PC
 SG_ S2P_DIAG_BYTE8_44 : 56|8@1+ (1,0) [0|255] ""  PC

BO_ 2416045677 S2P_DIAG__45: 8 SBMU
 SG_ S2P_DIAG_BYTE1_45 : 0|8@1+ (1,0) [0|255] ""  PC
 SG_ S2P_DIAG_BYTE2_45 : 8|8@1+ (1,0) [0|255] ""  PC
 SG_ S2P_DIAG_BYTE3_45 : 16|8@1+ (1,0) [0|255] ""  PC
 SG_ S2P_DIAG_BYTE4_45 : 24|8@1+ (1,0) [0|255] ""  PC
 SG_ S2P_DIAG_BYTE5_45 : 32|8@1+ (1,0) [0|255] ""  PC
 SG_ S2P_DIAG_BYTE6_45 : 40|8@1+ (1,0) [0|255] ""  PC
 SG_ S2P_DIAG_BYTE7_45 : 48|8@1+ (1,0) [0|255] ""  PC
 SG_ S2P_DIAG_BYTE8_45 : 56|8@1+ (1,0) [0|255] ""  PC

BO_ 2416045678 S2P_DIAG__46: 8 SBMU
 SG_ S2P_DIAG_BYTE1_46 : 0|8@1+ (1,0) [0|255] ""  PC
 SG_ S2P_DIAG_BYTE2_46 : 8|8@1+ (1,0) [0|255] ""  PC
 SG_ S2P_DIAG_BYTE3_46 : 16|8@1+ (1,0) [0|255] ""  PC
 SG_ S2P_DIAG_BYTE4_46 : 24|8@1+ (1,0) [0|255] ""  PC
 SG_ S2P_DIAG_BYTE5_46 : 32|8@1+ (1,0) [0|255] ""  PC
 SG_ S2P_DIAG_BYTE6_46 : 40|8@1+ (1,0) [0|255] ""  PC
 SG_ S2P_DIAG_BYTE7_46 : 48|8@1+ (1,0) [0|255] ""  PC
 SG_ S2P_DIAG_BYTE8_46 : 56|8@1+ (1,0) [0|255] ""  PC

BO_ 2416045679 S2P_DIAG__47: 8 SBMU
 SG_ S2P_DIAG_BYTE1_47 : 0|8@1+ (1,0) [0|255] ""  PC
 SG_ S2P_DIAG_BYTE2_47 : 8|8@1+ (1,0) [0|255] ""  PC
 SG_ S2P_DIAG_BYTE3_47 : 16|8@1+ (1,0) [0|255] ""  PC
 SG_ S2P_DIAG_BYTE4_47 : 24|8@1+ (1,0) [0|255] ""  PC
 SG_ S2P_DIAG_BYTE5_47 : 32|8@1+ (1,0) [0|255] ""  PC
 SG_ S2P_DIAG_BYTE6_47 : 40|8@1+ (1,0) [0|255] ""  PC
 SG_ S2P_DIAG_BYTE7_47 : 48|8@1+ (1,0) [0|255] ""  PC
 SG_ S2P_DIAG_BYTE8_47 : 56|8@1+ (1,0) [0|255] ""  PC

BO_ 2416045680 S2P_DIAG__48: 8 SBMU
 SG_ S2P_DIAG_BYTE1_48 : 0|8@1+ (1,0) [0|255] ""  PC
 SG_ S2P_DIAG_BYTE2_48 : 8|8@1+ (1,0) [0|255] ""  PC
 SG_ S2P_DIAG_BYTE3_48 : 16|8@1+ (1,0) [0|255] ""  PC
 SG_ S2P_DIAG_BYTE4_48 : 24|8@1+ (1,0) [0|255] ""  PC
 SG_ S2P_DIAG_BYTE5_48 : 32|8@1+ (1,0) [0|255] ""  PC
 SG_ S2P_DIAG_BYTE6_48 : 40|8@1+ (1,0) [0|255] ""  PC
 SG_ S2P_DIAG_BYTE7_48 : 48|8@1+ (1,0) [0|255] ""  PC
 SG_ S2P_DIAG_BYTE8_48 : 56|8@1+ (1,0) [0|255] ""  PC

BO_ 2416045681 S2P_DIAG__49: 8 SBMU
 SG_ S2P_DIAG_BYTE1_49 : 0|8@1+ (1,0) [0|255] ""  PC
 SG_ S2P_DIAG_BYTE2_49 : 8|8@1+ (1,0) [0|255] ""  PC
 SG_ S2P_DIAG_BYTE3_49 : 16|8@1+ (1,0) [0|255] ""  PC
 SG_ S2P_DIAG_BYTE4_49 : 24|8@1+ (1,0) [0|255] ""  PC
 SG_ S2P_DIAG_BYTE5_49 : 32|8@1+ (1,0) [0|255] ""  PC
 SG_ S2P_DIAG_BYTE6_49 : 40|8@1+ (1,0) [0|255] ""  PC
 SG_ S2P_DIAG_BYTE7_49 : 48|8@1+ (1,0) [0|255] ""  PC
 SG_ S2P_DIAG_BYTE8_49 : 56|8@1+ (1,0) [0|255] ""  PC

BO_ 2416045682 S2P_DIAG__50: 8 SBMU
 SG_ S2P_DIAG_BYTE1_50 : 0|8@1+ (1,0) [0|255] ""  PC
 SG_ S2P_DIAG_BYTE2_50 : 8|8@1+ (1,0) [0|255] ""  PC
 SG_ S2P_DIAG_BYTE3_50 : 16|8@1+ (1,0) [0|255] ""  PC
 SG_ S2P_DIAG_BYTE4_50 : 24|8@1+ (1,0) [0|255] ""  PC
 SG_ S2P_DIAG_BYTE5_50 : 32|8@1+ (1,0) [0|255] ""  PC
 SG_ S2P_DIAG_BYTE6_50 : 40|8@1+ (1,0) [0|255] ""  PC
 SG_ S2P_DIAG_BYTE7_50 : 48|8@1+ (1,0) [0|255] ""  PC
 SG_ S2P_DIAG_BYTE8_50 : 56|8@1+ (1,0) [0|255] ""  PC

BO_ 2416045683 S2P_DIAG__51: 8 SBMU
 SG_ S2P_DIAG_BYTE1_51 : 0|8@1+ (1,0) [0|255] ""  PC
 SG_ S2P_DIAG_BYTE2_51 : 8|8@1+ (1,0) [0|255] ""  PC
 SG_ S2P_DIAG_BYTE3_51 : 16|8@1+ (1,0) [0|255] ""  PC
 SG_ S2P_DIAG_BYTE4_51 : 24|8@1+ (1,0) [0|255] ""  PC
 SG_ S2P_DIAG_BYTE5_51 : 32|8@1+ (1,0) [0|255] ""  PC
 SG_ S2P_DIAG_BYTE6_51 : 40|8@1+ (1,0) [0|255] ""  PC
 SG_ S2P_DIAG_BYTE7_51 : 48|8@1+ (1,0) [0|255] ""  PC
 SG_ S2P_DIAG_BYTE8_51 : 56|8@1+ (1,0) [0|255] ""  PC

BO_ 2416045684 S2P_DIAG__52: 8 SBMU
 SG_ S2P_DIAG_BYTE1_52 : 0|8@1+ (1,0) [0|255] ""  PC
 SG_ S2P_DIAG_BYTE2_52 : 8|8@1+ (1,0) [0|255] ""  PC
 SG_ S2P_DIAG_BYTE3_52 : 16|8@1+ (1,0) [0|255] ""  PC
 SG_ S2P_DIAG_BYTE4_52 : 24|8@1+ (1,0) [0|255] ""  PC
 SG_ S2P_DIAG_BYTE5_52 : 32|8@1+ (1,0) [0|255] ""  PC
 SG_ S2P_DIAG_BYTE6_52 : 40|8@1+ (1,0) [0|255] ""  PC
 SG_ S2P_DIAG_BYTE7_52 : 48|8@1+ (1,0) [0|255] ""  PC
 SG_ S2P_DIAG_BYTE8_52 : 56|8@1+ (1,0) [0|255] ""  PC

BO_ 2416045685 S2P_DIAG__53: 8 SBMU
 SG_ S2P_DIAG_BYTE1_53 : 0|8@1+ (1,0) [0|255] ""  PC
 SG_ S2P_DIAG_BYTE2_53 : 8|8@1+ (1,0) [0|255] ""  PC
 SG_ S2P_DIAG_BYTE3_53 : 16|8@1+ (1,0) [0|255] ""  PC
 SG_ S2P_DIAG_BYTE4_53 : 24|8@1+ (1,0) [0|255] ""  PC
 SG_ S2P_DIAG_BYTE5_53 : 32|8@1+ (1,0) [0|255] ""  PC
 SG_ S2P_DIAG_BYTE6_53 : 40|8@1+ (1,0) [0|255] ""  PC
 SG_ S2P_DIAG_BYTE7_53 : 48|8@1+ (1,0) [0|255] ""  PC
 SG_ S2P_DIAG_BYTE8_53 : 56|8@1+ (1,0) [0|255] ""  PC

BO_ 2416045686 S2P_DIAG__54: 8 SBMU
 SG_ S2P_DIAG_BYTE1_54 : 0|8@1+ (1,0) [0|255] ""  PC
 SG_ S2P_DIAG_BYTE2_54 : 8|8@1+ (1,0) [0|255] ""  PC
 SG_ S2P_DIAG_BYTE3_54 : 16|8@1+ (1,0) [0|255] ""  PC
 SG_ S2P_DIAG_BYTE4_54 : 24|8@1+ (1,0) [0|255] ""  PC
 SG_ S2P_DIAG_BYTE5_54 : 32|8@1+ (1,0) [0|255] ""  PC
 SG_ S2P_DIAG_BYTE6_54 : 40|8@1+ (1,0) [0|255] ""  PC
 SG_ S2P_DIAG_BYTE7_54 : 48|8@1+ (1,0) [0|255] ""  PC
 SG_ S2P_DIAG_BYTE8_54 : 56|8@1+ (1,0) [0|255] ""  PC

BO_ 2416045687 S2P_DIAG__55: 8 SBMU
 SG_ S2P_DIAG_BYTE1_55 : 0|8@1+ (1,0) [0|255] ""  PC
 SG_ S2P_DIAG_BYTE2_55 : 8|8@1+ (1,0) [0|255] ""  PC
 SG_ S2P_DIAG_BYTE3_55 : 16|8@1+ (1,0) [0|255] ""  PC
 SG_ S2P_DIAG_BYTE4_55 : 24|8@1+ (1,0) [0|255] ""  PC
 SG_ S2P_DIAG_BYTE5_55 : 32|8@1+ (1,0) [0|255] ""  PC
 SG_ S2P_DIAG_BYTE6_55 : 40|8@1+ (1,0) [0|255] ""  PC
 SG_ S2P_DIAG_BYTE7_55 : 48|8@1+ (1,0) [0|255] ""  PC
 SG_ S2P_DIAG_BYTE8_55 : 56|8@1+ (1,0) [0|255] ""  PC

BO_ 2416045688 S2P_DIAG__56: 8 SBMU
 SG_ S2P_DIAG_BYTE1_56 : 0|8@1+ (1,0) [0|255] ""  PC
 SG_ S2P_DIAG_BYTE2_56 : 8|8@1+ (1,0) [0|255] ""  PC
 SG_ S2P_DIAG_BYTE3_56 : 16|8@1+ (1,0) [0|255] ""  PC
 SG_ S2P_DIAG_BYTE4_56 : 24|8@1+ (1,0) [0|255] ""  PC
 SG_ S2P_DIAG_BYTE5_56 : 32|8@1+ (1,0) [0|255] ""  PC
 SG_ S2P_DIAG_BYTE6_56 : 40|8@1+ (1,0) [0|255] ""  PC
 SG_ S2P_DIAG_BYTE7_56 : 48|8@1+ (1,0) [0|255] ""  PC
 SG_ S2P_DIAG_BYTE8_56 : 56|8@1+ (1,0) [0|255] ""  PC

BO_ 2416045689 S2P_DIAG__57: 8 SBMU
 SG_ S2P_DIAG_BYTE1_57 : 0|8@1+ (1,0) [0|255] ""  PC
 SG_ S2P_DIAG_BYTE2_57 : 8|8@1+ (1,0) [0|255] ""  PC
 SG_ S2P_DIAG_BYTE3_57 : 16|8@1+ (1,0) [0|255] ""  PC
 SG_ S2P_DIAG_BYTE4_57 : 24|8@1+ (1,0) [0|255] ""  PC
 SG_ S2P_DIAG_BYTE5_57 : 32|8@1+ (1,0) [0|255] ""  PC
 SG_ S2P_DIAG_BYTE6_57 : 40|8@1+ (1,0) [0|255] ""  PC
 SG_ S2P_DIAG_BYTE7_57 : 48|8@1+ (1,0) [0|255] ""  PC
 SG_ S2P_DIAG_BYTE8_57 : 56|8@1+ (1,0) [0|255] ""  PC

BO_ 2416045690 S2P_DIAG__58: 8 SBMU
 SG_ S2P_DIAG_BYTE1_58 : 0|8@1+ (1,0) [0|255] ""  PC
 SG_ S2P_DIAG_BYTE2_58 : 8|8@1+ (1,0) [0|255] ""  PC
 SG_ S2P_DIAG_BYTE3_58 : 16|8@1+ (1,0) [0|255] ""  PC
 SG_ S2P_DIAG_BYTE4_58 : 24|8@1+ (1,0) [0|255] ""  PC
 SG_ S2P_DIAG_BYTE5_58 : 32|8@1+ (1,0) [0|255] ""  PC
 SG_ S2P_DIAG_BYTE6_58 : 40|8@1+ (1,0) [0|255] ""  PC
 SG_ S2P_DIAG_BYTE7_58 : 48|8@1+ (1,0) [0|255] ""  PC
 SG_ S2P_DIAG_BYTE8_58 : 56|8@1+ (1,0) [0|255] ""  PC

BO_ 2416045691 S2P_DIAG__59: 8 SBMU
 SG_ S2P_DIAG_BYTE1_59 : 0|8@1+ (1,0) [0|255] ""  PC
 SG_ S2P_DIAG_BYTE2_59 : 8|8@1+ (1,0) [0|255] ""  PC
 SG_ S2P_DIAG_BYTE3_59 : 16|8@1+ (1,0) [0|255] ""  PC
 SG_ S2P_DIAG_BYTE4_59 : 24|8@1+ (1,0) [0|255] ""  PC
 SG_ S2P_DIAG_BYTE5_59 : 32|8@1+ (1,0) [0|255] ""  PC
 SG_ S2P_DIAG_BYTE6_59 : 40|8@1+ (1,0) [0|255] ""  PC
 SG_ S2P_DIAG_BYTE7_59 : 48|8@1+ (1,0) [0|255] ""  PC
 SG_ S2P_DIAG_BYTE8_59 : 56|8@1+ (1,0) [0|255] ""  PC

BO_ 2416045692 S2P_DIAG__60: 8 SBMU
 SG_ S2P_DIAG_BYTE1_60 : 0|8@1+ (1,0) [0|255] ""  PC
 SG_ S2P_DIAG_BYTE2_60 : 8|8@1+ (1,0) [0|255] ""  PC
 SG_ S2P_DIAG_BYTE3_60 : 16|8@1+ (1,0) [0|255] ""  PC
 SG_ S2P_DIAG_BYTE4_60 : 24|8@1+ (1,0) [0|255] ""  PC
 SG_ S2P_DIAG_BYTE5_60 : 32|8@1+ (1,0) [0|255] ""  PC
 SG_ S2P_DIAG_BYTE6_60 : 40|8@1+ (1,0) [0|255] ""  PC
 SG_ S2P_DIAG_BYTE7_60 : 48|8@1+ (1,0) [0|255] ""  PC
 SG_ S2P_DIAG_BYTE8_60 : 56|8@1+ (1,0) [0|255] ""  PC

BO_ 2416045693 S2P_DIAG__61: 8 SBMU
 SG_ S2P_DIAG_BYTE1_61 : 0|8@1+ (1,0) [0|255] ""  PC
 SG_ S2P_DIAG_BYTE2_61 : 8|8@1+ (1,0) [0|255] ""  PC
 SG_ S2P_DIAG_BYTE3_61 : 16|8@1+ (1,0) [0|255] ""  PC
 SG_ S2P_DIAG_BYTE4_61 : 24|8@1+ (1,0) [0|255] ""  PC
 SG_ S2P_DIAG_BYTE5_61 : 32|8@1+ (1,0) [0|255] ""  PC
 SG_ S2P_DIAG_BYTE6_61 : 40|8@1+ (1,0) [0|255] ""  PC
 SG_ S2P_DIAG_BYTE7_61 : 48|8@1+ (1,0) [0|255] ""  PC
 SG_ S2P_DIAG_BYTE8_61 : 56|8@1+ (1,0) [0|255] ""  PC

BO_ 2416045694 S2P_DIAG__62: 8 SBMU
 SG_ S2P_DIAG_BYTE1_62 : 0|8@1+ (1,0) [0|255] ""  PC
 SG_ S2P_DIAG_BYTE2_62 : 8|8@1+ (1,0) [0|255] ""  PC
 SG_ S2P_DIAG_BYTE3_62 : 16|8@1+ (1,0) [0|255] ""  PC
 SG_ S2P_DIAG_BYTE4_62 : 24|8@1+ (1,0) [0|255] ""  PC
 SG_ S2P_DIAG_BYTE5_62 : 32|8@1+ (1,0) [0|255] ""  PC
 SG_ S2P_DIAG_BYTE6_62 : 40|8@1+ (1,0) [0|255] ""  PC
 SG_ S2P_DIAG_BYTE7_62 : 48|8@1+ (1,0) [0|255] ""  PC
 SG_ S2P_DIAG_BYTE8_62 : 56|8@1+ (1,0) [0|255] ""  PC

BO_ 2416045695 S2P_DIAG__63: 8 SBMU
 SG_ S2P_DIAG_BYTE1_63 : 0|8@1+ (1,0) [0|255] ""  PC
 SG_ S2P_DIAG_BYTE2_63 : 8|8@1+ (1,0) [0|255] ""  PC
 SG_ S2P_DIAG_BYTE3_63 : 16|8@1+ (1,0) [0|255] ""  PC
 SG_ S2P_DIAG_BYTE4_63 : 24|8@1+ (1,0) [0|255] ""  PC
 SG_ S2P_DIAG_BYTE5_63 : 32|8@1+ (1,0) [0|255] ""  PC
 SG_ S2P_DIAG_BYTE6_63 : 40|8@1+ (1,0) [0|255] ""  PC
 SG_ S2P_DIAG_BYTE7_63 : 48|8@1+ (1,0) [0|255] ""  PC
 SG_ S2P_DIAG_BYTE8_63 : 56|8@1+ (1,0) [0|255] ""  PC

BO_ 2416111169 S2P_Cfg1__01: 8 SBMU
 SG_ S2P_Cfg1_SW_Ver_Byte1_01 : 0|8@1+ (1,0) [0|255] ""  PC
 SG_ S2P_Cfg1_SW_Ver_Byte2_01 : 8|8@1+ (1,0) [0|255] ""  PC
 SG_ S2P_Cfg1_SW_Ver_Byte3_01 : 16|8@1+ (1,0) [0|255] ""  PC
 SG_ S2P_Cfg1_SW_Ver_Byte4_01 : 24|8@1+ (1,0) [0|255] ""  PC
 SG_ S2P_Cfg1_SW_Ver_Byte5_01 : 32|8@1+ (1,0) [0|255] ""  PC
 SG_ S2P_Cfg1_SW_Ver_Byte6_01 : 40|8@1+ (1,0) [0|255] ""  PC
 SG_ S2P_Cfg1_SW_Ver_Byte7_01 : 48|8@1+ (1,0) [0|255] ""  PC
 SG_ S2P_Cfg1_SW_Ver_Byte8_01 : 56|8@1+ (1,0) [0|255] ""  PC

BO_ 2416111170 S2P_Cfg1__02: 8 SBMU
 SG_ S2P_Cfg1_SW_Ver_Byte1_02 : 0|8@1+ (1,0) [0|255] ""  PC
 SG_ S2P_Cfg1_SW_Ver_Byte2_02 : 8|8@1+ (1,0) [0|255] ""  PC
 SG_ S2P_Cfg1_SW_Ver_Byte3_02 : 16|8@1+ (1,0) [0|255] ""  PC
 SG_ S2P_Cfg1_SW_Ver_Byte4_02 : 24|8@1+ (1,0) [0|255] ""  PC
 SG_ S2P_Cfg1_SW_Ver_Byte5_02 : 32|8@1+ (1,0) [0|255] ""  PC
 SG_ S2P_Cfg1_SW_Ver_Byte6_02 : 40|8@1+ (1,0) [0|255] ""  PC
 SG_ S2P_Cfg1_SW_Ver_Byte7_02 : 48|8@1+ (1,0) [0|255] ""  PC
 SG_ S2P_Cfg1_SW_Ver_Byte8_02 : 56|8@1+ (1,0) [0|255] ""  PC

BO_ 2416111171 S2P_Cfg1__03: 8 SBMU
 SG_ S2P_Cfg1_SW_Ver_Byte1_03 : 0|8@1+ (1,0) [0|255] ""  PC
 SG_ S2P_Cfg1_SW_Ver_Byte2_03 : 8|8@1+ (1,0) [0|255] ""  PC
 SG_ S2P_Cfg1_SW_Ver_Byte3_03 : 16|8@1+ (1,0) [0|255] ""  PC
 SG_ S2P_Cfg1_SW_Ver_Byte4_03 : 24|8@1+ (1,0) [0|255] ""  PC
 SG_ S2P_Cfg1_SW_Ver_Byte5_03 : 32|8@1+ (1,0) [0|255] ""  PC
 SG_ S2P_Cfg1_SW_Ver_Byte6_03 : 40|8@1+ (1,0) [0|255] ""  PC
 SG_ S2P_Cfg1_SW_Ver_Byte7_03 : 48|8@1+ (1,0) [0|255] ""  PC
 SG_ S2P_Cfg1_SW_Ver_Byte8_03 : 56|8@1+ (1,0) [0|255] ""  PC

BO_ 2416111172 S2P_Cfg1__04: 8 SBMU
 SG_ S2P_Cfg1_SW_Ver_Byte1_04 : 0|8@1+ (1,0) [0|255] ""  PC
 SG_ S2P_Cfg1_SW_Ver_Byte2_04 : 8|8@1+ (1,0) [0|255] ""  PC
 SG_ S2P_Cfg1_SW_Ver_Byte3_04 : 16|8@1+ (1,0) [0|255] ""  PC
 SG_ S2P_Cfg1_SW_Ver_Byte4_04 : 24|8@1+ (1,0) [0|255] ""  PC
 SG_ S2P_Cfg1_SW_Ver_Byte5_04 : 32|8@1+ (1,0) [0|255] ""  PC
 SG_ S2P_Cfg1_SW_Ver_Byte6_04 : 40|8@1+ (1,0) [0|255] ""  PC
 SG_ S2P_Cfg1_SW_Ver_Byte7_04 : 48|8@1+ (1,0) [0|255] ""  PC
 SG_ S2P_Cfg1_SW_Ver_Byte8_04 : 56|8@1+ (1,0) [0|255] ""  PC

BO_ 2416111173 S2P_Cfg1__05: 8 SBMU
 SG_ S2P_Cfg1_SW_Ver_Byte1_05 : 0|8@1+ (1,0) [0|255] ""  PC
 SG_ S2P_Cfg1_SW_Ver_Byte2_05 : 8|8@1+ (1,0) [0|255] ""  PC
 SG_ S2P_Cfg1_SW_Ver_Byte3_05 : 16|8@1+ (1,0) [0|255] ""  PC
 SG_ S2P_Cfg1_SW_Ver_Byte4_05 : 24|8@1+ (1,0) [0|255] ""  PC
 SG_ S2P_Cfg1_SW_Ver_Byte5_05 : 32|8@1+ (1,0) [0|255] ""  PC
 SG_ S2P_Cfg1_SW_Ver_Byte6_05 : 40|8@1+ (1,0) [0|255] ""  PC
 SG_ S2P_Cfg1_SW_Ver_Byte7_05 : 48|8@1+ (1,0) [0|255] ""  PC
 SG_ S2P_Cfg1_SW_Ver_Byte8_05 : 56|8@1+ (1,0) [0|255] ""  PC

BO_ 2416111174 S2P_Cfg1__06: 8 SBMU
 SG_ S2P_Cfg1_SW_Ver_Byte1_06 : 0|8@1+ (1,0) [0|255] ""  PC
 SG_ S2P_Cfg1_SW_Ver_Byte2_06 : 8|8@1+ (1,0) [0|255] ""  PC
 SG_ S2P_Cfg1_SW_Ver_Byte3_06 : 16|8@1+ (1,0) [0|255] ""  PC
 SG_ S2P_Cfg1_SW_Ver_Byte4_06 : 24|8@1+ (1,0) [0|255] ""  PC
 SG_ S2P_Cfg1_SW_Ver_Byte5_06 : 32|8@1+ (1,0) [0|255] ""  PC
 SG_ S2P_Cfg1_SW_Ver_Byte6_06 : 40|8@1+ (1,0) [0|255] ""  PC
 SG_ S2P_Cfg1_SW_Ver_Byte7_06 : 48|8@1+ (1,0) [0|255] ""  PC
 SG_ S2P_Cfg1_SW_Ver_Byte8_06 : 56|8@1+ (1,0) [0|255] ""  PC

BO_ 2416111175 S2P_Cfg1__07: 8 SBMU
 SG_ S2P_Cfg1_SW_Ver_Byte1_07 : 0|8@1+ (1,0) [0|255] ""  PC
 SG_ S2P_Cfg1_SW_Ver_Byte2_07 : 8|8@1+ (1,0) [0|255] ""  PC
 SG_ S2P_Cfg1_SW_Ver_Byte3_07 : 16|8@1+ (1,0) [0|255] ""  PC
 SG_ S2P_Cfg1_SW_Ver_Byte4_07 : 24|8@1+ (1,0) [0|255] ""  PC
 SG_ S2P_Cfg1_SW_Ver_Byte5_07 : 32|8@1+ (1,0) [0|255] ""  PC
 SG_ S2P_Cfg1_SW_Ver_Byte6_07 : 40|8@1+ (1,0) [0|255] ""  PC
 SG_ S2P_Cfg1_SW_Ver_Byte7_07 : 48|8@1+ (1,0) [0|255] ""  PC
 SG_ S2P_Cfg1_SW_Ver_Byte8_07 : 56|8@1+ (1,0) [0|255] ""  PC

BO_ 2416111176 S2P_Cfg1__08: 8 SBMU
 SG_ S2P_Cfg1_SW_Ver_Byte1_08 : 0|8@1+ (1,0) [0|255] ""  PC
 SG_ S2P_Cfg1_SW_Ver_Byte2_08 : 8|8@1+ (1,0) [0|255] ""  PC
 SG_ S2P_Cfg1_SW_Ver_Byte3_08 : 16|8@1+ (1,0) [0|255] ""  PC
 SG_ S2P_Cfg1_SW_Ver_Byte4_08 : 24|8@1+ (1,0) [0|255] ""  PC
 SG_ S2P_Cfg1_SW_Ver_Byte5_08 : 32|8@1+ (1,0) [0|255] ""  PC
 SG_ S2P_Cfg1_SW_Ver_Byte6_08 : 40|8@1+ (1,0) [0|255] ""  PC
 SG_ S2P_Cfg1_SW_Ver_Byte7_08 : 48|8@1+ (1,0) [0|255] ""  PC
 SG_ S2P_Cfg1_SW_Ver_Byte8_08 : 56|8@1+ (1,0) [0|255] ""  PC

BO_ 2416111177 S2P_Cfg1__09: 8 SBMU
 SG_ S2P_Cfg1_SW_Ver_Byte1_09 : 0|8@1+ (1,0) [0|255] ""  PC
 SG_ S2P_Cfg1_SW_Ver_Byte2_09 : 8|8@1+ (1,0) [0|255] ""  PC
 SG_ S2P_Cfg1_SW_Ver_Byte3_09 : 16|8@1+ (1,0) [0|255] ""  PC
 SG_ S2P_Cfg1_SW_Ver_Byte4_09 : 24|8@1+ (1,0) [0|255] ""  PC
 SG_ S2P_Cfg1_SW_Ver_Byte5_09 : 32|8@1+ (1,0) [0|255] ""  PC
 SG_ S2P_Cfg1_SW_Ver_Byte6_09 : 40|8@1+ (1,0) [0|255] ""  PC
 SG_ S2P_Cfg1_SW_Ver_Byte7_09 : 48|8@1+ (1,0) [0|255] ""  PC
 SG_ S2P_Cfg1_SW_Ver_Byte8_09 : 56|8@1+ (1,0) [0|255] ""  PC

BO_ 2416111178 S2P_Cfg1__10: 8 SBMU
 SG_ S2P_Cfg1_SW_Ver_Byte1_10 : 0|8@1+ (1,0) [0|255] ""  PC
 SG_ S2P_Cfg1_SW_Ver_Byte2_10 : 8|8@1+ (1,0) [0|255] ""  PC
 SG_ S2P_Cfg1_SW_Ver_Byte3_10 : 16|8@1+ (1,0) [0|255] ""  PC
 SG_ S2P_Cfg1_SW_Ver_Byte4_10 : 24|8@1+ (1,0) [0|255] ""  PC
 SG_ S2P_Cfg1_SW_Ver_Byte5_10 : 32|8@1+ (1,0) [0|255] ""  PC
 SG_ S2P_Cfg1_SW_Ver_Byte6_10 : 40|8@1+ (1,0) [0|255] ""  PC
 SG_ S2P_Cfg1_SW_Ver_Byte7_10 : 48|8@1+ (1,0) [0|255] ""  PC
 SG_ S2P_Cfg1_SW_Ver_Byte8_10 : 56|8@1+ (1,0) [0|255] ""  PC

BO_ 2416111179 S2P_Cfg1__11: 8 SBMU
 SG_ S2P_Cfg1_SW_Ver_Byte1_11 : 0|8@1+ (1,0) [0|255] ""  PC
 SG_ S2P_Cfg1_SW_Ver_Byte2_11 : 8|8@1+ (1,0) [0|255] ""  PC
 SG_ S2P_Cfg1_SW_Ver_Byte3_11 : 16|8@1+ (1,0) [0|255] ""  PC
 SG_ S2P_Cfg1_SW_Ver_Byte4_11 : 24|8@1+ (1,0) [0|255] ""  PC
 SG_ S2P_Cfg1_SW_Ver_Byte5_11 : 32|8@1+ (1,0) [0|255] ""  PC
 SG_ S2P_Cfg1_SW_Ver_Byte6_11 : 40|8@1+ (1,0) [0|255] ""  PC
 SG_ S2P_Cfg1_SW_Ver_Byte7_11 : 48|8@1+ (1,0) [0|255] ""  PC
 SG_ S2P_Cfg1_SW_Ver_Byte8_11 : 56|8@1+ (1,0) [0|255] ""  PC

BO_ 2416111180 S2P_Cfg1__12: 8 SBMU
 SG_ S2P_Cfg1_SW_Ver_Byte1_12 : 0|8@1+ (1,0) [0|255] ""  PC
 SG_ S2P_Cfg1_SW_Ver_Byte2_12 : 8|8@1+ (1,0) [0|255] ""  PC
 SG_ S2P_Cfg1_SW_Ver_Byte3_12 : 16|8@1+ (1,0) [0|255] ""  PC
 SG_ S2P_Cfg1_SW_Ver_Byte4_12 : 24|8@1+ (1,0) [0|255] ""  PC
 SG_ S2P_Cfg1_SW_Ver_Byte5_12 : 32|8@1+ (1,0) [0|255] ""  PC
 SG_ S2P_Cfg1_SW_Ver_Byte6_12 : 40|8@1+ (1,0) [0|255] ""  PC
 SG_ S2P_Cfg1_SW_Ver_Byte7_12 : 48|8@1+ (1,0) [0|255] ""  PC
 SG_ S2P_Cfg1_SW_Ver_Byte8_12 : 56|8@1+ (1,0) [0|255] ""  PC

BO_ 2416111181 S2P_Cfg1__13: 8 SBMU
 SG_ S2P_Cfg1_SW_Ver_Byte1_13 : 0|8@1+ (1,0) [0|255] ""  PC
 SG_ S2P_Cfg1_SW_Ver_Byte2_13 : 8|8@1+ (1,0) [0|255] ""  PC
 SG_ S2P_Cfg1_SW_Ver_Byte3_13 : 16|8@1+ (1,0) [0|255] ""  PC
 SG_ S2P_Cfg1_SW_Ver_Byte4_13 : 24|8@1+ (1,0) [0|255] ""  PC
 SG_ S2P_Cfg1_SW_Ver_Byte5_13 : 32|8@1+ (1,0) [0|255] ""  PC
 SG_ S2P_Cfg1_SW_Ver_Byte6_13 : 40|8@1+ (1,0) [0|255] ""  PC
 SG_ S2P_Cfg1_SW_Ver_Byte7_13 : 48|8@1+ (1,0) [0|255] ""  PC
 SG_ S2P_Cfg1_SW_Ver_Byte8_13 : 56|8@1+ (1,0) [0|255] ""  PC

BO_ 2416111182 S2P_Cfg1__14: 8 SBMU
 SG_ S2P_Cfg1_SW_Ver_Byte1_14 : 0|8@1+ (1,0) [0|255] ""  PC
 SG_ S2P_Cfg1_SW_Ver_Byte2_14 : 8|8@1+ (1,0) [0|255] ""  PC
 SG_ S2P_Cfg1_SW_Ver_Byte3_14 : 16|8@1+ (1,0) [0|255] ""  PC
 SG_ S2P_Cfg1_SW_Ver_Byte4_14 : 24|8@1+ (1,0) [0|255] ""  PC
 SG_ S2P_Cfg1_SW_Ver_Byte5_14 : 32|8@1+ (1,0) [0|255] ""  PC
 SG_ S2P_Cfg1_SW_Ver_Byte6_14 : 40|8@1+ (1,0) [0|255] ""  PC
 SG_ S2P_Cfg1_SW_Ver_Byte7_14 : 48|8@1+ (1,0) [0|255] ""  PC
 SG_ S2P_Cfg1_SW_Ver_Byte8_14 : 56|8@1+ (1,0) [0|255] ""  PC

BO_ 2416111183 S2P_Cfg1__15: 8 SBMU
 SG_ S2P_Cfg1_SW_Ver_Byte1_15 : 0|8@1+ (1,0) [0|255] ""  PC
 SG_ S2P_Cfg1_SW_Ver_Byte2_15 : 8|8@1+ (1,0) [0|255] ""  PC
 SG_ S2P_Cfg1_SW_Ver_Byte3_15 : 16|8@1+ (1,0) [0|255] ""  PC
 SG_ S2P_Cfg1_SW_Ver_Byte4_15 : 24|8@1+ (1,0) [0|255] ""  PC
 SG_ S2P_Cfg1_SW_Ver_Byte5_15 : 32|8@1+ (1,0) [0|255] ""  PC
 SG_ S2P_Cfg1_SW_Ver_Byte6_15 : 40|8@1+ (1,0) [0|255] ""  PC
 SG_ S2P_Cfg1_SW_Ver_Byte7_15 : 48|8@1+ (1,0) [0|255] ""  PC
 SG_ S2P_Cfg1_SW_Ver_Byte8_15 : 56|8@1+ (1,0) [0|255] ""  PC

BO_ 2416111184 S2P_Cfg1__16: 8 SBMU
 SG_ S2P_Cfg1_SW_Ver_Byte1_16 : 0|8@1+ (1,0) [0|255] ""  PC
 SG_ S2P_Cfg1_SW_Ver_Byte2_16 : 8|8@1+ (1,0) [0|255] ""  PC
 SG_ S2P_Cfg1_SW_Ver_Byte3_16 : 16|8@1+ (1,0) [0|255] ""  PC
 SG_ S2P_Cfg1_SW_Ver_Byte4_16 : 24|8@1+ (1,0) [0|255] ""  PC
 SG_ S2P_Cfg1_SW_Ver_Byte5_16 : 32|8@1+ (1,0) [0|255] ""  PC
 SG_ S2P_Cfg1_SW_Ver_Byte6_16 : 40|8@1+ (1,0) [0|255] ""  PC
 SG_ S2P_Cfg1_SW_Ver_Byte7_16 : 48|8@1+ (1,0) [0|255] ""  PC
 SG_ S2P_Cfg1_SW_Ver_Byte8_16 : 56|8@1+ (1,0) [0|255] ""  PC

BO_ 2416111185 S2P_Cfg1__17: 8 SBMU
 SG_ S2P_Cfg1_SW_Ver_Byte1_17 : 0|8@1+ (1,0) [0|255] ""  PC
 SG_ S2P_Cfg1_SW_Ver_Byte2_17 : 8|8@1+ (1,0) [0|255] ""  PC
 SG_ S2P_Cfg1_SW_Ver_Byte3_17 : 16|8@1+ (1,0) [0|255] ""  PC
 SG_ S2P_Cfg1_SW_Ver_Byte4_17 : 24|8@1+ (1,0) [0|255] ""  PC
 SG_ S2P_Cfg1_SW_Ver_Byte5_17 : 32|8@1+ (1,0) [0|255] ""  PC
 SG_ S2P_Cfg1_SW_Ver_Byte6_17 : 40|8@1+ (1,0) [0|255] ""  PC
 SG_ S2P_Cfg1_SW_Ver_Byte7_17 : 48|8@1+ (1,0) [0|255] ""  PC
 SG_ S2P_Cfg1_SW_Ver_Byte8_17 : 56|8@1+ (1,0) [0|255] ""  PC

BO_ 2416111186 S2P_Cfg1__18: 8 SBMU
 SG_ S2P_Cfg1_SW_Ver_Byte1_18 : 0|8@1+ (1,0) [0|255] ""  PC
 SG_ S2P_Cfg1_SW_Ver_Byte2_18 : 8|8@1+ (1,0) [0|255] ""  PC
 SG_ S2P_Cfg1_SW_Ver_Byte3_18 : 16|8@1+ (1,0) [0|255] ""  PC
 SG_ S2P_Cfg1_SW_Ver_Byte4_18 : 24|8@1+ (1,0) [0|255] ""  PC
 SG_ S2P_Cfg1_SW_Ver_Byte5_18 : 32|8@1+ (1,0) [0|255] ""  PC
 SG_ S2P_Cfg1_SW_Ver_Byte6_18 : 40|8@1+ (1,0) [0|255] ""  PC
 SG_ S2P_Cfg1_SW_Ver_Byte7_18 : 48|8@1+ (1,0) [0|255] ""  PC
 SG_ S2P_Cfg1_SW_Ver_Byte8_18 : 56|8@1+ (1,0) [0|255] ""  PC

BO_ 2416111187 S2P_Cfg1__19: 8 SBMU
 SG_ S2P_Cfg1_SW_Ver_Byte1_19 : 0|8@1+ (1,0) [0|255] ""  PC
 SG_ S2P_Cfg1_SW_Ver_Byte2_19 : 8|8@1+ (1,0) [0|255] ""  PC
 SG_ S2P_Cfg1_SW_Ver_Byte3_19 : 16|8@1+ (1,0) [0|255] ""  PC
 SG_ S2P_Cfg1_SW_Ver_Byte4_19 : 24|8@1+ (1,0) [0|255] ""  PC
 SG_ S2P_Cfg1_SW_Ver_Byte5_19 : 32|8@1+ (1,0) [0|255] ""  PC
 SG_ S2P_Cfg1_SW_Ver_Byte6_19 : 40|8@1+ (1,0) [0|255] ""  PC
 SG_ S2P_Cfg1_SW_Ver_Byte7_19 : 48|8@1+ (1,0) [0|255] ""  PC
 SG_ S2P_Cfg1_SW_Ver_Byte8_19 : 56|8@1+ (1,0) [0|255] ""  PC

BO_ 2416111188 S2P_Cfg1__20: 8 SBMU
 SG_ S2P_Cfg1_SW_Ver_Byte1_20 : 0|8@1+ (1,0) [0|255] ""  PC
 SG_ S2P_Cfg1_SW_Ver_Byte2_20 : 8|8@1+ (1,0) [0|255] ""  PC
 SG_ S2P_Cfg1_SW_Ver_Byte3_20 : 16|8@1+ (1,0) [0|255] ""  PC
 SG_ S2P_Cfg1_SW_Ver_Byte4_20 : 24|8@1+ (1,0) [0|255] ""  PC
 SG_ S2P_Cfg1_SW_Ver_Byte5_20 : 32|8@1+ (1,0) [0|255] ""  PC
 SG_ S2P_Cfg1_SW_Ver_Byte6_20 : 40|8@1+ (1,0) [0|255] ""  PC
 SG_ S2P_Cfg1_SW_Ver_Byte7_20 : 48|8@1+ (1,0) [0|255] ""  PC
 SG_ S2P_Cfg1_SW_Ver_Byte8_20 : 56|8@1+ (1,0) [0|255] ""  PC

BO_ 2416111189 S2P_Cfg1__21: 8 SBMU
 SG_ S2P_Cfg1_SW_Ver_Byte1_21 : 0|8@1+ (1,0) [0|255] ""  PC
 SG_ S2P_Cfg1_SW_Ver_Byte2_21 : 8|8@1+ (1,0) [0|255] ""  PC
 SG_ S2P_Cfg1_SW_Ver_Byte3_21 : 16|8@1+ (1,0) [0|255] ""  PC
 SG_ S2P_Cfg1_SW_Ver_Byte4_21 : 24|8@1+ (1,0) [0|255] ""  PC
 SG_ S2P_Cfg1_SW_Ver_Byte5_21 : 32|8@1+ (1,0) [0|255] ""  PC
 SG_ S2P_Cfg1_SW_Ver_Byte6_21 : 40|8@1+ (1,0) [0|255] ""  PC
 SG_ S2P_Cfg1_SW_Ver_Byte7_21 : 48|8@1+ (1,0) [0|255] ""  PC
 SG_ S2P_Cfg1_SW_Ver_Byte8_21 : 56|8@1+ (1,0) [0|255] ""  PC

BO_ 2416111190 S2P_Cfg1__22: 8 SBMU
 SG_ S2P_Cfg1_SW_Ver_Byte1_22 : 0|8@1+ (1,0) [0|255] ""  PC
 SG_ S2P_Cfg1_SW_Ver_Byte2_22 : 8|8@1+ (1,0) [0|255] ""  PC
 SG_ S2P_Cfg1_SW_Ver_Byte3_22 : 16|8@1+ (1,0) [0|255] ""  PC
 SG_ S2P_Cfg1_SW_Ver_Byte4_22 : 24|8@1+ (1,0) [0|255] ""  PC
 SG_ S2P_Cfg1_SW_Ver_Byte5_22 : 32|8@1+ (1,0) [0|255] ""  PC
 SG_ S2P_Cfg1_SW_Ver_Byte6_22 : 40|8@1+ (1,0) [0|255] ""  PC
 SG_ S2P_Cfg1_SW_Ver_Byte7_22 : 48|8@1+ (1,0) [0|255] ""  PC
 SG_ S2P_Cfg1_SW_Ver_Byte8_22 : 56|8@1+ (1,0) [0|255] ""  PC

BO_ 2416111191 S2P_Cfg1__23: 8 SBMU
 SG_ S2P_Cfg1_SW_Ver_Byte1_23 : 0|8@1+ (1,0) [0|255] ""  PC
 SG_ S2P_Cfg1_SW_Ver_Byte2_23 : 8|8@1+ (1,0) [0|255] ""  PC
 SG_ S2P_Cfg1_SW_Ver_Byte3_23 : 16|8@1+ (1,0) [0|255] ""  PC
 SG_ S2P_Cfg1_SW_Ver_Byte4_23 : 24|8@1+ (1,0) [0|255] ""  PC
 SG_ S2P_Cfg1_SW_Ver_Byte5_23 : 32|8@1+ (1,0) [0|255] ""  PC
 SG_ S2P_Cfg1_SW_Ver_Byte6_23 : 40|8@1+ (1,0) [0|255] ""  PC
 SG_ S2P_Cfg1_SW_Ver_Byte7_23 : 48|8@1+ (1,0) [0|255] ""  PC
 SG_ S2P_Cfg1_SW_Ver_Byte8_23 : 56|8@1+ (1,0) [0|255] ""  PC

BO_ 2416111192 S2P_Cfg1__24: 8 SBMU
 SG_ S2P_Cfg1_SW_Ver_Byte1_24 : 0|8@1+ (1,0) [0|255] ""  PC
 SG_ S2P_Cfg1_SW_Ver_Byte2_24 : 8|8@1+ (1,0) [0|255] ""  PC
 SG_ S2P_Cfg1_SW_Ver_Byte3_24 : 16|8@1+ (1,0) [0|255] ""  PC
 SG_ S2P_Cfg1_SW_Ver_Byte4_24 : 24|8@1+ (1,0) [0|255] ""  PC
 SG_ S2P_Cfg1_SW_Ver_Byte5_24 : 32|8@1+ (1,0) [0|255] ""  PC
 SG_ S2P_Cfg1_SW_Ver_Byte6_24 : 40|8@1+ (1,0) [0|255] ""  PC
 SG_ S2P_Cfg1_SW_Ver_Byte7_24 : 48|8@1+ (1,0) [0|255] ""  PC
 SG_ S2P_Cfg1_SW_Ver_Byte8_24 : 56|8@1+ (1,0) [0|255] ""  PC

BO_ 2416111193 S2P_Cfg1__25: 8 SBMU
 SG_ S2P_Cfg1_SW_Ver_Byte1_25 : 0|8@1+ (1,0) [0|255] ""  PC
 SG_ S2P_Cfg1_SW_Ver_Byte2_25 : 8|8@1+ (1,0) [0|255] ""  PC
 SG_ S2P_Cfg1_SW_Ver_Byte3_25 : 16|8@1+ (1,0) [0|255] ""  PC
 SG_ S2P_Cfg1_SW_Ver_Byte4_25 : 24|8@1+ (1,0) [0|255] ""  PC
 SG_ S2P_Cfg1_SW_Ver_Byte5_25 : 32|8@1+ (1,0) [0|255] ""  PC
 SG_ S2P_Cfg1_SW_Ver_Byte6_25 : 40|8@1+ (1,0) [0|255] ""  PC
 SG_ S2P_Cfg1_SW_Ver_Byte7_25 : 48|8@1+ (1,0) [0|255] ""  PC
 SG_ S2P_Cfg1_SW_Ver_Byte8_25 : 56|8@1+ (1,0) [0|255] ""  PC

BO_ 2416111194 S2P_Cfg1__26: 8 SBMU
 SG_ S2P_Cfg1_SW_Ver_Byte1_26 : 0|8@1+ (1,0) [0|255] ""  PC
 SG_ S2P_Cfg1_SW_Ver_Byte2_26 : 8|8@1+ (1,0) [0|255] ""  PC
 SG_ S2P_Cfg1_SW_Ver_Byte3_26 : 16|8@1+ (1,0) [0|255] ""  PC
 SG_ S2P_Cfg1_SW_Ver_Byte4_26 : 24|8@1+ (1,0) [0|255] ""  PC
 SG_ S2P_Cfg1_SW_Ver_Byte5_26 : 32|8@1+ (1,0) [0|255] ""  PC
 SG_ S2P_Cfg1_SW_Ver_Byte6_26 : 40|8@1+ (1,0) [0|255] ""  PC
 SG_ S2P_Cfg1_SW_Ver_Byte7_26 : 48|8@1+ (1,0) [0|255] ""  PC
 SG_ S2P_Cfg1_SW_Ver_Byte8_26 : 56|8@1+ (1,0) [0|255] ""  PC

BO_ 2416111195 S2P_Cfg1__27: 8 SBMU
 SG_ S2P_Cfg1_SW_Ver_Byte1_27 : 0|8@1+ (1,0) [0|255] ""  PC
 SG_ S2P_Cfg1_SW_Ver_Byte2_27 : 8|8@1+ (1,0) [0|255] ""  PC
 SG_ S2P_Cfg1_SW_Ver_Byte3_27 : 16|8@1+ (1,0) [0|255] ""  PC
 SG_ S2P_Cfg1_SW_Ver_Byte4_27 : 24|8@1+ (1,0) [0|255] ""  PC
 SG_ S2P_Cfg1_SW_Ver_Byte5_27 : 32|8@1+ (1,0) [0|255] ""  PC
 SG_ S2P_Cfg1_SW_Ver_Byte6_27 : 40|8@1+ (1,0) [0|255] ""  PC
 SG_ S2P_Cfg1_SW_Ver_Byte7_27 : 48|8@1+ (1,0) [0|255] ""  PC
 SG_ S2P_Cfg1_SW_Ver_Byte8_27 : 56|8@1+ (1,0) [0|255] ""  PC

BO_ 2416111196 S2P_Cfg1__28: 8 SBMU
 SG_ S2P_Cfg1_SW_Ver_Byte1_28 : 0|8@1+ (1,0) [0|255] ""  PC
 SG_ S2P_Cfg1_SW_Ver_Byte2_28 : 8|8@1+ (1,0) [0|255] ""  PC
 SG_ S2P_Cfg1_SW_Ver_Byte3_28 : 16|8@1+ (1,0) [0|255] ""  PC
 SG_ S2P_Cfg1_SW_Ver_Byte4_28 : 24|8@1+ (1,0) [0|255] ""  PC
 SG_ S2P_Cfg1_SW_Ver_Byte5_28 : 32|8@1+ (1,0) [0|255] ""  PC
 SG_ S2P_Cfg1_SW_Ver_Byte6_28 : 40|8@1+ (1,0) [0|255] ""  PC
 SG_ S2P_Cfg1_SW_Ver_Byte7_28 : 48|8@1+ (1,0) [0|255] ""  PC
 SG_ S2P_Cfg1_SW_Ver_Byte8_28 : 56|8@1+ (1,0) [0|255] ""  PC

BO_ 2416111197 S2P_Cfg1__29: 8 SBMU
 SG_ S2P_Cfg1_SW_Ver_Byte1_29 : 0|8@1+ (1,0) [0|255] ""  PC
 SG_ S2P_Cfg1_SW_Ver_Byte2_29 : 8|8@1+ (1,0) [0|255] ""  PC
 SG_ S2P_Cfg1_SW_Ver_Byte3_29 : 16|8@1+ (1,0) [0|255] ""  PC
 SG_ S2P_Cfg1_SW_Ver_Byte4_29 : 24|8@1+ (1,0) [0|255] ""  PC
 SG_ S2P_Cfg1_SW_Ver_Byte5_29 : 32|8@1+ (1,0) [0|255] ""  PC
 SG_ S2P_Cfg1_SW_Ver_Byte6_29 : 40|8@1+ (1,0) [0|255] ""  PC
 SG_ S2P_Cfg1_SW_Ver_Byte7_29 : 48|8@1+ (1,0) [0|255] ""  PC
 SG_ S2P_Cfg1_SW_Ver_Byte8_29 : 56|8@1+ (1,0) [0|255] ""  PC

BO_ 2416111198 S2P_Cfg1__30: 8 SBMU
 SG_ S2P_Cfg1_SW_Ver_Byte1_30 : 0|8@1+ (1,0) [0|255] ""  PC
 SG_ S2P_Cfg1_SW_Ver_Byte2_30 : 8|8@1+ (1,0) [0|255] ""  PC
 SG_ S2P_Cfg1_SW_Ver_Byte3_30 : 16|8@1+ (1,0) [0|255] ""  PC
 SG_ S2P_Cfg1_SW_Ver_Byte4_30 : 24|8@1+ (1,0) [0|255] ""  PC
 SG_ S2P_Cfg1_SW_Ver_Byte5_30 : 32|8@1+ (1,0) [0|255] ""  PC
 SG_ S2P_Cfg1_SW_Ver_Byte6_30 : 40|8@1+ (1,0) [0|255] ""  PC
 SG_ S2P_Cfg1_SW_Ver_Byte7_30 : 48|8@1+ (1,0) [0|255] ""  PC
 SG_ S2P_Cfg1_SW_Ver_Byte8_30 : 56|8@1+ (1,0) [0|255] ""  PC

BO_ 2416111199 S2P_Cfg1__31: 8 SBMU
 SG_ S2P_Cfg1_SW_Ver_Byte1_31 : 0|8@1+ (1,0) [0|255] ""  PC
 SG_ S2P_Cfg1_SW_Ver_Byte2_31 : 8|8@1+ (1,0) [0|255] ""  PC
 SG_ S2P_Cfg1_SW_Ver_Byte3_31 : 16|8@1+ (1,0) [0|255] ""  PC
 SG_ S2P_Cfg1_SW_Ver_Byte4_31 : 24|8@1+ (1,0) [0|255] ""  PC
 SG_ S2P_Cfg1_SW_Ver_Byte5_31 : 32|8@1+ (1,0) [0|255] ""  PC
 SG_ S2P_Cfg1_SW_Ver_Byte6_31 : 40|8@1+ (1,0) [0|255] ""  PC
 SG_ S2P_Cfg1_SW_Ver_Byte7_31 : 48|8@1+ (1,0) [0|255] ""  PC
 SG_ S2P_Cfg1_SW_Ver_Byte8_31 : 56|8@1+ (1,0) [0|255] ""  PC

BO_ 2416111200 S2P_Cfg1__32: 8 SBMU
 SG_ S2P_Cfg1_SW_Ver_Byte1_32 : 0|8@1+ (1,0) [0|255] ""  PC
 SG_ S2P_Cfg1_SW_Ver_Byte2_32 : 8|8@1+ (1,0) [0|255] ""  PC
 SG_ S2P_Cfg1_SW_Ver_Byte3_32 : 16|8@1+ (1,0) [0|255] ""  PC
 SG_ S2P_Cfg1_SW_Ver_Byte4_32 : 24|8@1+ (1,0) [0|255] ""  PC
 SG_ S2P_Cfg1_SW_Ver_Byte5_32 : 32|8@1+ (1,0) [0|255] ""  PC
 SG_ S2P_Cfg1_SW_Ver_Byte6_32 : 40|8@1+ (1,0) [0|255] ""  PC
 SG_ S2P_Cfg1_SW_Ver_Byte7_32 : 48|8@1+ (1,0) [0|255] ""  PC
 SG_ S2P_Cfg1_SW_Ver_Byte8_32 : 56|8@1+ (1,0) [0|255] ""  PC

BO_ 2416111201 S2P_Cfg1__33: 8 SBMU
 SG_ S2P_Cfg1_SW_Ver_Byte1_33 : 0|8@1+ (1,0) [0|255] ""  PC
 SG_ S2P_Cfg1_SW_Ver_Byte2_33 : 8|8@1+ (1,0) [0|255] ""  PC
 SG_ S2P_Cfg1_SW_Ver_Byte3_33 : 16|8@1+ (1,0) [0|255] ""  PC
 SG_ S2P_Cfg1_SW_Ver_Byte4_33 : 24|8@1+ (1,0) [0|255] ""  PC
 SG_ S2P_Cfg1_SW_Ver_Byte5_33 : 32|8@1+ (1,0) [0|255] ""  PC
 SG_ S2P_Cfg1_SW_Ver_Byte6_33 : 40|8@1+ (1,0) [0|255] ""  PC
 SG_ S2P_Cfg1_SW_Ver_Byte7_33 : 48|8@1+ (1,0) [0|255] ""  PC
 SG_ S2P_Cfg1_SW_Ver_Byte8_33 : 56|8@1+ (1,0) [0|255] ""  PC

BO_ 2416111202 S2P_Cfg1__34: 8 SBMU
 SG_ S2P_Cfg1_SW_Ver_Byte1_34 : 0|8@1+ (1,0) [0|255] ""  PC
 SG_ S2P_Cfg1_SW_Ver_Byte2_34 : 8|8@1+ (1,0) [0|255] ""  PC
 SG_ S2P_Cfg1_SW_Ver_Byte3_34 : 16|8@1+ (1,0) [0|255] ""  PC
 SG_ S2P_Cfg1_SW_Ver_Byte4_34 : 24|8@1+ (1,0) [0|255] ""  PC
 SG_ S2P_Cfg1_SW_Ver_Byte5_34 : 32|8@1+ (1,0) [0|255] ""  PC
 SG_ S2P_Cfg1_SW_Ver_Byte6_34 : 40|8@1+ (1,0) [0|255] ""  PC
 SG_ S2P_Cfg1_SW_Ver_Byte7_34 : 48|8@1+ (1,0) [0|255] ""  PC
 SG_ S2P_Cfg1_SW_Ver_Byte8_34 : 56|8@1+ (1,0) [0|255] ""  PC

BO_ 2416111203 S2P_Cfg1__35: 8 SBMU
 SG_ S2P_Cfg1_SW_Ver_Byte1_35 : 0|8@1+ (1,0) [0|255] ""  PC
 SG_ S2P_Cfg1_SW_Ver_Byte2_35 : 8|8@1+ (1,0) [0|255] ""  PC
 SG_ S2P_Cfg1_SW_Ver_Byte3_35 : 16|8@1+ (1,0) [0|255] ""  PC
 SG_ S2P_Cfg1_SW_Ver_Byte4_35 : 24|8@1+ (1,0) [0|255] ""  PC
 SG_ S2P_Cfg1_SW_Ver_Byte5_35 : 32|8@1+ (1,0) [0|255] ""  PC
 SG_ S2P_Cfg1_SW_Ver_Byte6_35 : 40|8@1+ (1,0) [0|255] ""  PC
 SG_ S2P_Cfg1_SW_Ver_Byte7_35 : 48|8@1+ (1,0) [0|255] ""  PC
 SG_ S2P_Cfg1_SW_Ver_Byte8_35 : 56|8@1+ (1,0) [0|255] ""  PC

BO_ 2416111204 S2P_Cfg1__36: 8 SBMU
 SG_ S2P_Cfg1_SW_Ver_Byte1_36 : 0|8@1+ (1,0) [0|255] ""  PC
 SG_ S2P_Cfg1_SW_Ver_Byte2_36 : 8|8@1+ (1,0) [0|255] ""  PC
 SG_ S2P_Cfg1_SW_Ver_Byte3_36 : 16|8@1+ (1,0) [0|255] ""  PC
 SG_ S2P_Cfg1_SW_Ver_Byte4_36 : 24|8@1+ (1,0) [0|255] ""  PC
 SG_ S2P_Cfg1_SW_Ver_Byte5_36 : 32|8@1+ (1,0) [0|255] ""  PC
 SG_ S2P_Cfg1_SW_Ver_Byte6_36 : 40|8@1+ (1,0) [0|255] ""  PC
 SG_ S2P_Cfg1_SW_Ver_Byte7_36 : 48|8@1+ (1,0) [0|255] ""  PC
 SG_ S2P_Cfg1_SW_Ver_Byte8_36 : 56|8@1+ (1,0) [0|255] ""  PC

BO_ 2416111205 S2P_Cfg1__37: 8 SBMU
 SG_ S2P_Cfg1_SW_Ver_Byte1_37 : 0|8@1+ (1,0) [0|255] ""  PC
 SG_ S2P_Cfg1_SW_Ver_Byte2_37 : 8|8@1+ (1,0) [0|255] ""  PC
 SG_ S2P_Cfg1_SW_Ver_Byte3_37 : 16|8@1+ (1,0) [0|255] ""  PC
 SG_ S2P_Cfg1_SW_Ver_Byte4_37 : 24|8@1+ (1,0) [0|255] ""  PC
 SG_ S2P_Cfg1_SW_Ver_Byte5_37 : 32|8@1+ (1,0) [0|255] ""  PC
 SG_ S2P_Cfg1_SW_Ver_Byte6_37 : 40|8@1+ (1,0) [0|255] ""  PC
 SG_ S2P_Cfg1_SW_Ver_Byte7_37 : 48|8@1+ (1,0) [0|255] ""  PC
 SG_ S2P_Cfg1_SW_Ver_Byte8_37 : 56|8@1+ (1,0) [0|255] ""  PC

BO_ 2416111206 S2P_Cfg1__38: 8 SBMU
 SG_ S2P_Cfg1_SW_Ver_Byte1_38 : 0|8@1+ (1,0) [0|255] ""  PC
 SG_ S2P_Cfg1_SW_Ver_Byte2_38 : 8|8@1+ (1,0) [0|255] ""  PC
 SG_ S2P_Cfg1_SW_Ver_Byte3_38 : 16|8@1+ (1,0) [0|255] ""  PC
 SG_ S2P_Cfg1_SW_Ver_Byte4_38 : 24|8@1+ (1,0) [0|255] ""  PC
 SG_ S2P_Cfg1_SW_Ver_Byte5_38 : 32|8@1+ (1,0) [0|255] ""  PC
 SG_ S2P_Cfg1_SW_Ver_Byte6_38 : 40|8@1+ (1,0) [0|255] ""  PC
 SG_ S2P_Cfg1_SW_Ver_Byte7_38 : 48|8@1+ (1,0) [0|255] ""  PC
 SG_ S2P_Cfg1_SW_Ver_Byte8_38 : 56|8@1+ (1,0) [0|255] ""  PC

BO_ 2416111207 S2P_Cfg1__39: 8 SBMU
 SG_ S2P_Cfg1_SW_Ver_Byte1_39 : 0|8@1+ (1,0) [0|255] ""  PC
 SG_ S2P_Cfg1_SW_Ver_Byte2_39 : 8|8@1+ (1,0) [0|255] ""  PC
 SG_ S2P_Cfg1_SW_Ver_Byte3_39 : 16|8@1+ (1,0) [0|255] ""  PC
 SG_ S2P_Cfg1_SW_Ver_Byte4_39 : 24|8@1+ (1,0) [0|255] ""  PC
 SG_ S2P_Cfg1_SW_Ver_Byte5_39 : 32|8@1+ (1,0) [0|255] ""  PC
 SG_ S2P_Cfg1_SW_Ver_Byte6_39 : 40|8@1+ (1,0) [0|255] ""  PC
 SG_ S2P_Cfg1_SW_Ver_Byte7_39 : 48|8@1+ (1,0) [0|255] ""  PC
 SG_ S2P_Cfg1_SW_Ver_Byte8_39 : 56|8@1+ (1,0) [0|255] ""  PC

BO_ 2416111208 S2P_Cfg1__40: 8 SBMU
 SG_ S2P_Cfg1_SW_Ver_Byte1_40 : 0|8@1+ (1,0) [0|255] ""  PC
 SG_ S2P_Cfg1_SW_Ver_Byte2_40 : 8|8@1+ (1,0) [0|255] ""  PC
 SG_ S2P_Cfg1_SW_Ver_Byte3_40 : 16|8@1+ (1,0) [0|255] ""  PC
 SG_ S2P_Cfg1_SW_Ver_Byte4_40 : 24|8@1+ (1,0) [0|255] ""  PC
 SG_ S2P_Cfg1_SW_Ver_Byte5_40 : 32|8@1+ (1,0) [0|255] ""  PC
 SG_ S2P_Cfg1_SW_Ver_Byte6_40 : 40|8@1+ (1,0) [0|255] ""  PC
 SG_ S2P_Cfg1_SW_Ver_Byte7_40 : 48|8@1+ (1,0) [0|255] ""  PC
 SG_ S2P_Cfg1_SW_Ver_Byte8_40 : 56|8@1+ (1,0) [0|255] ""  PC

BO_ 2416111209 S2P_Cfg1__41: 8 SBMU
 SG_ S2P_Cfg1_SW_Ver_Byte1_41 : 0|8@1+ (1,0) [0|255] ""  PC
 SG_ S2P_Cfg1_SW_Ver_Byte2_41 : 8|8@1+ (1,0) [0|255] ""  PC
 SG_ S2P_Cfg1_SW_Ver_Byte3_41 : 16|8@1+ (1,0) [0|255] ""  PC
 SG_ S2P_Cfg1_SW_Ver_Byte4_41 : 24|8@1+ (1,0) [0|255] ""  PC
 SG_ S2P_Cfg1_SW_Ver_Byte5_41 : 32|8@1+ (1,0) [0|255] ""  PC
 SG_ S2P_Cfg1_SW_Ver_Byte6_41 : 40|8@1+ (1,0) [0|255] ""  PC
 SG_ S2P_Cfg1_SW_Ver_Byte7_41 : 48|8@1+ (1,0) [0|255] ""  PC
 SG_ S2P_Cfg1_SW_Ver_Byte8_41 : 56|8@1+ (1,0) [0|255] ""  PC

BO_ 2416111210 S2P_Cfg1__42: 8 SBMU
 SG_ S2P_Cfg1_SW_Ver_Byte1_42 : 0|8@1+ (1,0) [0|255] ""  PC
 SG_ S2P_Cfg1_SW_Ver_Byte2_42 : 8|8@1+ (1,0) [0|255] ""  PC
 SG_ S2P_Cfg1_SW_Ver_Byte3_42 : 16|8@1+ (1,0) [0|255] ""  PC
 SG_ S2P_Cfg1_SW_Ver_Byte4_42 : 24|8@1+ (1,0) [0|255] ""  PC
 SG_ S2P_Cfg1_SW_Ver_Byte5_42 : 32|8@1+ (1,0) [0|255] ""  PC
 SG_ S2P_Cfg1_SW_Ver_Byte6_42 : 40|8@1+ (1,0) [0|255] ""  PC
 SG_ S2P_Cfg1_SW_Ver_Byte7_42 : 48|8@1+ (1,0) [0|255] ""  PC
 SG_ S2P_Cfg1_SW_Ver_Byte8_42 : 56|8@1+ (1,0) [0|255] ""  PC

BO_ 2416111211 S2P_Cfg1__43: 8 SBMU
 SG_ S2P_Cfg1_SW_Ver_Byte1_43 : 0|8@1+ (1,0) [0|255] ""  PC
 SG_ S2P_Cfg1_SW_Ver_Byte2_43 : 8|8@1+ (1,0) [0|255] ""  PC
 SG_ S2P_Cfg1_SW_Ver_Byte3_43 : 16|8@1+ (1,0) [0|255] ""  PC
 SG_ S2P_Cfg1_SW_Ver_Byte4_43 : 24|8@1+ (1,0) [0|255] ""  PC
 SG_ S2P_Cfg1_SW_Ver_Byte5_43 : 32|8@1+ (1,0) [0|255] ""  PC
 SG_ S2P_Cfg1_SW_Ver_Byte6_43 : 40|8@1+ (1,0) [0|255] ""  PC
 SG_ S2P_Cfg1_SW_Ver_Byte7_43 : 48|8@1+ (1,0) [0|255] ""  PC
 SG_ S2P_Cfg1_SW_Ver_Byte8_43 : 56|8@1+ (1,0) [0|255] ""  PC

BO_ 2416111212 S2P_Cfg1__44: 8 SBMU
 SG_ S2P_Cfg1_SW_Ver_Byte1_44 : 0|8@1+ (1,0) [0|255] ""  PC
 SG_ S2P_Cfg1_SW_Ver_Byte2_44 : 8|8@1+ (1,0) [0|255] ""  PC
 SG_ S2P_Cfg1_SW_Ver_Byte3_44 : 16|8@1+ (1,0) [0|255] ""  PC
 SG_ S2P_Cfg1_SW_Ver_Byte4_44 : 24|8@1+ (1,0) [0|255] ""  PC
 SG_ S2P_Cfg1_SW_Ver_Byte5_44 : 32|8@1+ (1,0) [0|255] ""  PC
 SG_ S2P_Cfg1_SW_Ver_Byte6_44 : 40|8@1+ (1,0) [0|255] ""  PC
 SG_ S2P_Cfg1_SW_Ver_Byte7_44 : 48|8@1+ (1,0) [0|255] ""  PC
 SG_ S2P_Cfg1_SW_Ver_Byte8_44 : 56|8@1+ (1,0) [0|255] ""  PC

BO_ 2416111213 S2P_Cfg1__45: 8 SBMU
 SG_ S2P_Cfg1_SW_Ver_Byte1_45 : 0|8@1+ (1,0) [0|255] ""  PC
 SG_ S2P_Cfg1_SW_Ver_Byte2_45 : 8|8@1+ (1,0) [0|255] ""  PC
 SG_ S2P_Cfg1_SW_Ver_Byte3_45 : 16|8@1+ (1,0) [0|255] ""  PC
 SG_ S2P_Cfg1_SW_Ver_Byte4_45 : 24|8@1+ (1,0) [0|255] ""  PC
 SG_ S2P_Cfg1_SW_Ver_Byte5_45 : 32|8@1+ (1,0) [0|255] ""  PC
 SG_ S2P_Cfg1_SW_Ver_Byte6_45 : 40|8@1+ (1,0) [0|255] ""  PC
 SG_ S2P_Cfg1_SW_Ver_Byte7_45 : 48|8@1+ (1,0) [0|255] ""  PC
 SG_ S2P_Cfg1_SW_Ver_Byte8_45 : 56|8@1+ (1,0) [0|255] ""  PC

BO_ 2416111214 S2P_Cfg1__46: 8 SBMU
 SG_ S2P_Cfg1_SW_Ver_Byte1_46 : 0|8@1+ (1,0) [0|255] ""  PC
 SG_ S2P_Cfg1_SW_Ver_Byte2_46 : 8|8@1+ (1,0) [0|255] ""  PC
 SG_ S2P_Cfg1_SW_Ver_Byte3_46 : 16|8@1+ (1,0) [0|255] ""  PC
 SG_ S2P_Cfg1_SW_Ver_Byte4_46 : 24|8@1+ (1,0) [0|255] ""  PC
 SG_ S2P_Cfg1_SW_Ver_Byte5_46 : 32|8@1+ (1,0) [0|255] ""  PC
 SG_ S2P_Cfg1_SW_Ver_Byte6_46 : 40|8@1+ (1,0) [0|255] ""  PC
 SG_ S2P_Cfg1_SW_Ver_Byte7_46 : 48|8@1+ (1,0) [0|255] ""  PC
 SG_ S2P_Cfg1_SW_Ver_Byte8_46 : 56|8@1+ (1,0) [0|255] ""  PC

BO_ 2416111215 S2P_Cfg1__47: 8 SBMU
 SG_ S2P_Cfg1_SW_Ver_Byte1_47 : 0|8@1+ (1,0) [0|255] ""  PC
 SG_ S2P_Cfg1_SW_Ver_Byte2_47 : 8|8@1+ (1,0) [0|255] ""  PC
 SG_ S2P_Cfg1_SW_Ver_Byte3_47 : 16|8@1+ (1,0) [0|255] ""  PC
 SG_ S2P_Cfg1_SW_Ver_Byte4_47 : 24|8@1+ (1,0) [0|255] ""  PC
 SG_ S2P_Cfg1_SW_Ver_Byte5_47 : 32|8@1+ (1,0) [0|255] ""  PC
 SG_ S2P_Cfg1_SW_Ver_Byte6_47 : 40|8@1+ (1,0) [0|255] ""  PC
 SG_ S2P_Cfg1_SW_Ver_Byte7_47 : 48|8@1+ (1,0) [0|255] ""  PC
 SG_ S2P_Cfg1_SW_Ver_Byte8_47 : 56|8@1+ (1,0) [0|255] ""  PC

BO_ 2416111216 S2P_Cfg1__48: 8 SBMU
 SG_ S2P_Cfg1_SW_Ver_Byte1_48 : 0|8@1+ (1,0) [0|255] ""  PC
 SG_ S2P_Cfg1_SW_Ver_Byte2_48 : 8|8@1+ (1,0) [0|255] ""  PC
 SG_ S2P_Cfg1_SW_Ver_Byte3_48 : 16|8@1+ (1,0) [0|255] ""  PC
 SG_ S2P_Cfg1_SW_Ver_Byte4_48 : 24|8@1+ (1,0) [0|255] ""  PC
 SG_ S2P_Cfg1_SW_Ver_Byte5_48 : 32|8@1+ (1,0) [0|255] ""  PC
 SG_ S2P_Cfg1_SW_Ver_Byte6_48 : 40|8@1+ (1,0) [0|255] ""  PC
 SG_ S2P_Cfg1_SW_Ver_Byte7_48 : 48|8@1+ (1,0) [0|255] ""  PC
 SG_ S2P_Cfg1_SW_Ver_Byte8_48 : 56|8@1+ (1,0) [0|255] ""  PC

BO_ 2416111217 S2P_Cfg1__49: 8 SBMU
 SG_ S2P_Cfg1_SW_Ver_Byte1_49 : 0|8@1+ (1,0) [0|255] ""  PC
 SG_ S2P_Cfg1_SW_Ver_Byte2_49 : 8|8@1+ (1,0) [0|255] ""  PC
 SG_ S2P_Cfg1_SW_Ver_Byte3_49 : 16|8@1+ (1,0) [0|255] ""  PC
 SG_ S2P_Cfg1_SW_Ver_Byte4_49 : 24|8@1+ (1,0) [0|255] ""  PC
 SG_ S2P_Cfg1_SW_Ver_Byte5_49 : 32|8@1+ (1,0) [0|255] ""  PC
 SG_ S2P_Cfg1_SW_Ver_Byte6_49 : 40|8@1+ (1,0) [0|255] ""  PC
 SG_ S2P_Cfg1_SW_Ver_Byte7_49 : 48|8@1+ (1,0) [0|255] ""  PC
 SG_ S2P_Cfg1_SW_Ver_Byte8_49 : 56|8@1+ (1,0) [0|255] ""  PC

BO_ 2416111218 S2P_Cfg1__50: 8 SBMU
 SG_ S2P_Cfg1_SW_Ver_Byte1_50 : 0|8@1+ (1,0) [0|255] ""  PC
 SG_ S2P_Cfg1_SW_Ver_Byte2_50 : 8|8@1+ (1,0) [0|255] ""  PC
 SG_ S2P_Cfg1_SW_Ver_Byte3_50 : 16|8@1+ (1,0) [0|255] ""  PC
 SG_ S2P_Cfg1_SW_Ver_Byte4_50 : 24|8@1+ (1,0) [0|255] ""  PC
 SG_ S2P_Cfg1_SW_Ver_Byte5_50 : 32|8@1+ (1,0) [0|255] ""  PC
 SG_ S2P_Cfg1_SW_Ver_Byte6_50 : 40|8@1+ (1,0) [0|255] ""  PC
 SG_ S2P_Cfg1_SW_Ver_Byte7_50 : 48|8@1+ (1,0) [0|255] ""  PC
 SG_ S2P_Cfg1_SW_Ver_Byte8_50 : 56|8@1+ (1,0) [0|255] ""  PC

BO_ 2416111219 S2P_Cfg1__51: 8 SBMU
 SG_ S2P_Cfg1_SW_Ver_Byte1_51 : 0|8@1+ (1,0) [0|255] ""  PC
 SG_ S2P_Cfg1_SW_Ver_Byte2_51 : 8|8@1+ (1,0) [0|255] ""  PC
 SG_ S2P_Cfg1_SW_Ver_Byte3_51 : 16|8@1+ (1,0) [0|255] ""  PC
 SG_ S2P_Cfg1_SW_Ver_Byte4_51 : 24|8@1+ (1,0) [0|255] ""  PC
 SG_ S2P_Cfg1_SW_Ver_Byte5_51 : 32|8@1+ (1,0) [0|255] ""  PC
 SG_ S2P_Cfg1_SW_Ver_Byte6_51 : 40|8@1+ (1,0) [0|255] ""  PC
 SG_ S2P_Cfg1_SW_Ver_Byte7_51 : 48|8@1+ (1,0) [0|255] ""  PC
 SG_ S2P_Cfg1_SW_Ver_Byte8_51 : 56|8@1+ (1,0) [0|255] ""  PC

BO_ 2416111220 S2P_Cfg1__52: 8 SBMU
 SG_ S2P_Cfg1_SW_Ver_Byte1_52 : 0|8@1+ (1,0) [0|255] ""  PC
 SG_ S2P_Cfg1_SW_Ver_Byte2_52 : 8|8@1+ (1,0) [0|255] ""  PC
 SG_ S2P_Cfg1_SW_Ver_Byte3_52 : 16|8@1+ (1,0) [0|255] ""  PC
 SG_ S2P_Cfg1_SW_Ver_Byte4_52 : 24|8@1+ (1,0) [0|255] ""  PC
 SG_ S2P_Cfg1_SW_Ver_Byte5_52 : 32|8@1+ (1,0) [0|255] ""  PC
 SG_ S2P_Cfg1_SW_Ver_Byte6_52 : 40|8@1+ (1,0) [0|255] ""  PC
 SG_ S2P_Cfg1_SW_Ver_Byte7_52 : 48|8@1+ (1,0) [0|255] ""  PC
 SG_ S2P_Cfg1_SW_Ver_Byte8_52 : 56|8@1+ (1,0) [0|255] ""  PC

BO_ 2416111221 S2P_Cfg1__53: 8 SBMU
 SG_ S2P_Cfg1_SW_Ver_Byte1_53 : 0|8@1+ (1,0) [0|255] ""  PC
 SG_ S2P_Cfg1_SW_Ver_Byte2_53 : 8|8@1+ (1,0) [0|255] ""  PC
 SG_ S2P_Cfg1_SW_Ver_Byte3_53 : 16|8@1+ (1,0) [0|255] ""  PC
 SG_ S2P_Cfg1_SW_Ver_Byte4_53 : 24|8@1+ (1,0) [0|255] ""  PC
 SG_ S2P_Cfg1_SW_Ver_Byte5_53 : 32|8@1+ (1,0) [0|255] ""  PC
 SG_ S2P_Cfg1_SW_Ver_Byte6_53 : 40|8@1+ (1,0) [0|255] ""  PC
 SG_ S2P_Cfg1_SW_Ver_Byte7_53 : 48|8@1+ (1,0) [0|255] ""  PC
 SG_ S2P_Cfg1_SW_Ver_Byte8_53 : 56|8@1+ (1,0) [0|255] ""  PC

BO_ 2416111222 S2P_Cfg1__54: 8 SBMU
 SG_ S2P_Cfg1_SW_Ver_Byte1_54 : 0|8@1+ (1,0) [0|255] ""  PC
 SG_ S2P_Cfg1_SW_Ver_Byte2_54 : 8|8@1+ (1,0) [0|255] ""  PC
 SG_ S2P_Cfg1_SW_Ver_Byte3_54 : 16|8@1+ (1,0) [0|255] ""  PC
 SG_ S2P_Cfg1_SW_Ver_Byte4_54 : 24|8@1+ (1,0) [0|255] ""  PC
 SG_ S2P_Cfg1_SW_Ver_Byte5_54 : 32|8@1+ (1,0) [0|255] ""  PC
 SG_ S2P_Cfg1_SW_Ver_Byte6_54 : 40|8@1+ (1,0) [0|255] ""  PC
 SG_ S2P_Cfg1_SW_Ver_Byte7_54 : 48|8@1+ (1,0) [0|255] ""  PC
 SG_ S2P_Cfg1_SW_Ver_Byte8_54 : 56|8@1+ (1,0) [0|255] ""  PC

BO_ 2416111223 S2P_Cfg1__55: 8 SBMU
 SG_ S2P_Cfg1_SW_Ver_Byte1_55 : 0|8@1+ (1,0) [0|255] ""  PC
 SG_ S2P_Cfg1_SW_Ver_Byte2_55 : 8|8@1+ (1,0) [0|255] ""  PC
 SG_ S2P_Cfg1_SW_Ver_Byte3_55 : 16|8@1+ (1,0) [0|255] ""  PC
 SG_ S2P_Cfg1_SW_Ver_Byte4_55 : 24|8@1+ (1,0) [0|255] ""  PC
 SG_ S2P_Cfg1_SW_Ver_Byte5_55 : 32|8@1+ (1,0) [0|255] ""  PC
 SG_ S2P_Cfg1_SW_Ver_Byte6_55 : 40|8@1+ (1,0) [0|255] ""  PC
 SG_ S2P_Cfg1_SW_Ver_Byte7_55 : 48|8@1+ (1,0) [0|255] ""  PC
 SG_ S2P_Cfg1_SW_Ver_Byte8_55 : 56|8@1+ (1,0) [0|255] ""  PC

BO_ 2416111224 S2P_Cfg1__56: 8 SBMU
 SG_ S2P_Cfg1_SW_Ver_Byte1_56 : 0|8@1+ (1,0) [0|255] ""  PC
 SG_ S2P_Cfg1_SW_Ver_Byte2_56 : 8|8@1+ (1,0) [0|255] ""  PC
 SG_ S2P_Cfg1_SW_Ver_Byte3_56 : 16|8@1+ (1,0) [0|255] ""  PC
 SG_ S2P_Cfg1_SW_Ver_Byte4_56 : 24|8@1+ (1,0) [0|255] ""  PC
 SG_ S2P_Cfg1_SW_Ver_Byte5_56 : 32|8@1+ (1,0) [0|255] ""  PC
 SG_ S2P_Cfg1_SW_Ver_Byte6_56 : 40|8@1+ (1,0) [0|255] ""  PC
 SG_ S2P_Cfg1_SW_Ver_Byte7_56 : 48|8@1+ (1,0) [0|255] ""  PC
 SG_ S2P_Cfg1_SW_Ver_Byte8_56 : 56|8@1+ (1,0) [0|255] ""  PC

BO_ 2416111225 S2P_Cfg1__57: 8 SBMU
 SG_ S2P_Cfg1_SW_Ver_Byte1_57 : 0|8@1+ (1,0) [0|255] ""  PC
 SG_ S2P_Cfg1_SW_Ver_Byte2_57 : 8|8@1+ (1,0) [0|255] ""  PC
 SG_ S2P_Cfg1_SW_Ver_Byte3_57 : 16|8@1+ (1,0) [0|255] ""  PC
 SG_ S2P_Cfg1_SW_Ver_Byte4_57 : 24|8@1+ (1,0) [0|255] ""  PC
 SG_ S2P_Cfg1_SW_Ver_Byte5_57 : 32|8@1+ (1,0) [0|255] ""  PC
 SG_ S2P_Cfg1_SW_Ver_Byte6_57 : 40|8@1+ (1,0) [0|255] ""  PC
 SG_ S2P_Cfg1_SW_Ver_Byte7_57 : 48|8@1+ (1,0) [0|255] ""  PC
 SG_ S2P_Cfg1_SW_Ver_Byte8_57 : 56|8@1+ (1,0) [0|255] ""  PC

BO_ 2416111226 S2P_Cfg1__58: 8 SBMU
 SG_ S2P_Cfg1_SW_Ver_Byte1_58 : 0|8@1+ (1,0) [0|255] ""  PC
 SG_ S2P_Cfg1_SW_Ver_Byte2_58 : 8|8@1+ (1,0) [0|255] ""  PC
 SG_ S2P_Cfg1_SW_Ver_Byte3_58 : 16|8@1+ (1,0) [0|255] ""  PC
 SG_ S2P_Cfg1_SW_Ver_Byte4_58 : 24|8@1+ (1,0) [0|255] ""  PC
 SG_ S2P_Cfg1_SW_Ver_Byte5_58 : 32|8@1+ (1,0) [0|255] ""  PC
 SG_ S2P_Cfg1_SW_Ver_Byte6_58 : 40|8@1+ (1,0) [0|255] ""  PC
 SG_ S2P_Cfg1_SW_Ver_Byte7_58 : 48|8@1+ (1,0) [0|255] ""  PC
 SG_ S2P_Cfg1_SW_Ver_Byte8_58 : 56|8@1+ (1,0) [0|255] ""  PC

BO_ 2416111227 S2P_Cfg1__59: 8 SBMU
 SG_ S2P_Cfg1_SW_Ver_Byte1_59 : 0|8@1+ (1,0) [0|255] ""  PC
 SG_ S2P_Cfg1_SW_Ver_Byte2_59 : 8|8@1+ (1,0) [0|255] ""  PC
 SG_ S2P_Cfg1_SW_Ver_Byte3_59 : 16|8@1+ (1,0) [0|255] ""  PC
 SG_ S2P_Cfg1_SW_Ver_Byte4_59 : 24|8@1+ (1,0) [0|255] ""  PC
 SG_ S2P_Cfg1_SW_Ver_Byte5_59 : 32|8@1+ (1,0) [0|255] ""  PC
 SG_ S2P_Cfg1_SW_Ver_Byte6_59 : 40|8@1+ (1,0) [0|255] ""  PC
 SG_ S2P_Cfg1_SW_Ver_Byte7_59 : 48|8@1+ (1,0) [0|255] ""  PC
 SG_ S2P_Cfg1_SW_Ver_Byte8_59 : 56|8@1+ (1,0) [0|255] ""  PC

BO_ 2416111228 S2P_Cfg1__60: 8 SBMU
 SG_ S2P_Cfg1_SW_Ver_Byte1_60 : 0|8@1+ (1,0) [0|255] ""  PC
 SG_ S2P_Cfg1_SW_Ver_Byte2_60 : 8|8@1+ (1,0) [0|255] ""  PC
 SG_ S2P_Cfg1_SW_Ver_Byte3_60 : 16|8@1+ (1,0) [0|255] ""  PC
 SG_ S2P_Cfg1_SW_Ver_Byte4_60 : 24|8@1+ (1,0) [0|255] ""  PC
 SG_ S2P_Cfg1_SW_Ver_Byte5_60 : 32|8@1+ (1,0) [0|255] ""  PC
 SG_ S2P_Cfg1_SW_Ver_Byte6_60 : 40|8@1+ (1,0) [0|255] ""  PC
 SG_ S2P_Cfg1_SW_Ver_Byte7_60 : 48|8@1+ (1,0) [0|255] ""  PC
 SG_ S2P_Cfg1_SW_Ver_Byte8_60 : 56|8@1+ (1,0) [0|255] ""  PC

BO_ 2416111229 S2P_Cfg1__61: 8 SBMU
 SG_ S2P_Cfg1_SW_Ver_Byte1_61 : 0|8@1+ (1,0) [0|255] ""  PC
 SG_ S2P_Cfg1_SW_Ver_Byte2_61 : 8|8@1+ (1,0) [0|255] ""  PC
 SG_ S2P_Cfg1_SW_Ver_Byte3_61 : 16|8@1+ (1,0) [0|255] ""  PC
 SG_ S2P_Cfg1_SW_Ver_Byte4_61 : 24|8@1+ (1,0) [0|255] ""  PC
 SG_ S2P_Cfg1_SW_Ver_Byte5_61 : 32|8@1+ (1,0) [0|255] ""  PC
 SG_ S2P_Cfg1_SW_Ver_Byte6_61 : 40|8@1+ (1,0) [0|255] ""  PC
 SG_ S2P_Cfg1_SW_Ver_Byte7_61 : 48|8@1+ (1,0) [0|255] ""  PC
 SG_ S2P_Cfg1_SW_Ver_Byte8_61 : 56|8@1+ (1,0) [0|255] ""  PC

BO_ 2416111230 S2P_Cfg1__62: 8 SBMU
 SG_ S2P_Cfg1_SW_Ver_Byte1_62 : 0|8@1+ (1,0) [0|255] ""  PC
 SG_ S2P_Cfg1_SW_Ver_Byte2_62 : 8|8@1+ (1,0) [0|255] ""  PC
 SG_ S2P_Cfg1_SW_Ver_Byte3_62 : 16|8@1+ (1,0) [0|255] ""  PC
 SG_ S2P_Cfg1_SW_Ver_Byte4_62 : 24|8@1+ (1,0) [0|255] ""  PC
 SG_ S2P_Cfg1_SW_Ver_Byte5_62 : 32|8@1+ (1,0) [0|255] ""  PC
 SG_ S2P_Cfg1_SW_Ver_Byte6_62 : 40|8@1+ (1,0) [0|255] ""  PC
 SG_ S2P_Cfg1_SW_Ver_Byte7_62 : 48|8@1+ (1,0) [0|255] ""  PC
 SG_ S2P_Cfg1_SW_Ver_Byte8_62 : 56|8@1+ (1,0) [0|255] ""  PC

BO_ 2416111231 S2P_Cfg1__63: 8 SBMU
 SG_ S2P_Cfg1_SW_Ver_Byte1_63 : 0|8@1+ (1,0) [0|255] ""  PC
 SG_ S2P_Cfg1_SW_Ver_Byte2_63 : 8|8@1+ (1,0) [0|255] ""  PC
 SG_ S2P_Cfg1_SW_Ver_Byte3_63 : 16|8@1+ (1,0) [0|255] ""  PC
 SG_ S2P_Cfg1_SW_Ver_Byte4_63 : 24|8@1+ (1,0) [0|255] ""  PC
 SG_ S2P_Cfg1_SW_Ver_Byte5_63 : 32|8@1+ (1,0) [0|255] ""  PC
 SG_ S2P_Cfg1_SW_Ver_Byte6_63 : 40|8@1+ (1,0) [0|255] ""  PC
 SG_ S2P_Cfg1_SW_Ver_Byte7_63 : 48|8@1+ (1,0) [0|255] ""  PC
 SG_ S2P_Cfg1_SW_Ver_Byte8_63 : 56|8@1+ (1,0) [0|255] ""  PC

BO_ 2416176705 S2P_Cfg2__01: 8 SBMU
 SG_ S2P_Cfg2_SW_Ver_Byte9_01 : 0|8@1+ (1,0) [0|255] ""  PC
 SG_ S2P_Cfg2_SW_Ver_Byte10_01 : 8|8@1+ (1,0) [0|255] ""  PC
 SG_ S2P_Cfg2_SW_Ver_Byte11_01 : 16|8@1+ (1,0) [0|255] ""  PC
 SG_ S2P_Cfg2_SW_Ver_Byte12_01 : 24|8@1+ (1,0) [0|255] ""  PC
 SG_ S2P_Cfg2_SW_Ver_Byte13_01 : 32|8@1+ (1,0) [0|255] ""  PC
 SG_ S2P_Cfg2_SW_Ver_Byte14_01 : 40|8@1+ (1,0) [0|255] ""  PC
 SG_ S2P_Cfg2_SW_Ver_Byte15_01 : 48|8@1+ (1,0) [0|255] ""  PC
 SG_ S2P_Cfg2_SW_Ver_Byte16_01 : 56|8@1+ (1,0) [0|255] ""  PC

BO_ 2416176706 S2P_Cfg2__02: 8 SBMU
 SG_ S2P_Cfg2_SW_Ver_Byte9_02 : 0|8@1+ (1,0) [0|255] ""  PC
 SG_ S2P_Cfg2_SW_Ver_Byte10_02 : 8|8@1+ (1,0) [0|255] ""  PC
 SG_ S2P_Cfg2_SW_Ver_Byte11_02 : 16|8@1+ (1,0) [0|255] ""  PC
 SG_ S2P_Cfg2_SW_Ver_Byte12_02 : 24|8@1+ (1,0) [0|255] ""  PC
 SG_ S2P_Cfg2_SW_Ver_Byte13_02 : 32|8@1+ (1,0) [0|255] ""  PC
 SG_ S2P_Cfg2_SW_Ver_Byte14_02 : 40|8@1+ (1,0) [0|255] ""  PC
 SG_ S2P_Cfg2_SW_Ver_Byte15_02 : 48|8@1+ (1,0) [0|255] ""  PC
 SG_ S2P_Cfg2_SW_Ver_Byte16_02 : 56|8@1+ (1,0) [0|255] ""  PC

BO_ 2416176707 S2P_Cfg2__03: 8 SBMU
 SG_ S2P_Cfg2_SW_Ver_Byte9_03 : 0|8@1+ (1,0) [0|255] ""  PC
 SG_ S2P_Cfg2_SW_Ver_Byte10_03 : 8|8@1+ (1,0) [0|255] ""  PC
 SG_ S2P_Cfg2_SW_Ver_Byte11_03 : 16|8@1+ (1,0) [0|255] ""  PC
 SG_ S2P_Cfg2_SW_Ver_Byte12_03 : 24|8@1+ (1,0) [0|255] ""  PC
 SG_ S2P_Cfg2_SW_Ver_Byte13_03 : 32|8@1+ (1,0) [0|255] ""  PC
 SG_ S2P_Cfg2_SW_Ver_Byte14_03 : 40|8@1+ (1,0) [0|255] ""  PC
 SG_ S2P_Cfg2_SW_Ver_Byte15_03 : 48|8@1+ (1,0) [0|255] ""  PC
 SG_ S2P_Cfg2_SW_Ver_Byte16_03 : 56|8@1+ (1,0) [0|255] ""  PC

BO_ 2416176708 S2P_Cfg2__04: 8 SBMU
 SG_ S2P_Cfg2_SW_Ver_Byte9_04 : 0|8@1+ (1,0) [0|255] ""  PC
 SG_ S2P_Cfg2_SW_Ver_Byte10_04 : 8|8@1+ (1,0) [0|255] ""  PC
 SG_ S2P_Cfg2_SW_Ver_Byte11_04 : 16|8@1+ (1,0) [0|255] ""  PC
 SG_ S2P_Cfg2_SW_Ver_Byte12_04 : 24|8@1+ (1,0) [0|255] ""  PC
 SG_ S2P_Cfg2_SW_Ver_Byte13_04 : 32|8@1+ (1,0) [0|255] ""  PC
 SG_ S2P_Cfg2_SW_Ver_Byte14_04 : 40|8@1+ (1,0) [0|255] ""  PC
 SG_ S2P_Cfg2_SW_Ver_Byte15_04 : 48|8@1+ (1,0) [0|255] ""  PC
 SG_ S2P_Cfg2_SW_Ver_Byte16_04 : 56|8@1+ (1,0) [0|255] ""  PC

BO_ 2416176709 S2P_Cfg2__05: 8 SBMU
 SG_ S2P_Cfg2_SW_Ver_Byte9_05 : 0|8@1+ (1,0) [0|255] ""  PC
 SG_ S2P_Cfg2_SW_Ver_Byte10_05 : 8|8@1+ (1,0) [0|255] ""  PC
 SG_ S2P_Cfg2_SW_Ver_Byte11_05 : 16|8@1+ (1,0) [0|255] ""  PC
 SG_ S2P_Cfg2_SW_Ver_Byte12_05 : 24|8@1+ (1,0) [0|255] ""  PC
 SG_ S2P_Cfg2_SW_Ver_Byte13_05 : 32|8@1+ (1,0) [0|255] ""  PC
 SG_ S2P_Cfg2_SW_Ver_Byte14_05 : 40|8@1+ (1,0) [0|255] ""  PC
 SG_ S2P_Cfg2_SW_Ver_Byte15_05 : 48|8@1+ (1,0) [0|255] ""  PC
 SG_ S2P_Cfg2_SW_Ver_Byte16_05 : 56|8@1+ (1,0) [0|255] ""  PC

BO_ 2416176710 S2P_Cfg2__06: 8 SBMU
 SG_ S2P_Cfg2_SW_Ver_Byte9_06 : 0|8@1+ (1,0) [0|255] ""  PC
 SG_ S2P_Cfg2_SW_Ver_Byte10_06 : 8|8@1+ (1,0) [0|255] ""  PC
 SG_ S2P_Cfg2_SW_Ver_Byte11_06 : 16|8@1+ (1,0) [0|255] ""  PC
 SG_ S2P_Cfg2_SW_Ver_Byte12_06 : 24|8@1+ (1,0) [0|255] ""  PC
 SG_ S2P_Cfg2_SW_Ver_Byte13_06 : 32|8@1+ (1,0) [0|255] ""  PC
 SG_ S2P_Cfg2_SW_Ver_Byte14_06 : 40|8@1+ (1,0) [0|255] ""  PC
 SG_ S2P_Cfg2_SW_Ver_Byte15_06 : 48|8@1+ (1,0) [0|255] ""  PC
 SG_ S2P_Cfg2_SW_Ver_Byte16_06 : 56|8@1+ (1,0) [0|255] ""  PC

BO_ 2416176711 S2P_Cfg2__07: 8 SBMU
 SG_ S2P_Cfg2_SW_Ver_Byte9_07 : 0|8@1+ (1,0) [0|255] ""  PC
 SG_ S2P_Cfg2_SW_Ver_Byte10_07 : 8|8@1+ (1,0) [0|255] ""  PC
 SG_ S2P_Cfg2_SW_Ver_Byte11_07 : 16|8@1+ (1,0) [0|255] ""  PC
 SG_ S2P_Cfg2_SW_Ver_Byte12_07 : 24|8@1+ (1,0) [0|255] ""  PC
 SG_ S2P_Cfg2_SW_Ver_Byte13_07 : 32|8@1+ (1,0) [0|255] ""  PC
 SG_ S2P_Cfg2_SW_Ver_Byte14_07 : 40|8@1+ (1,0) [0|255] ""  PC
 SG_ S2P_Cfg2_SW_Ver_Byte15_07 : 48|8@1+ (1,0) [0|255] ""  PC
 SG_ S2P_Cfg2_SW_Ver_Byte16_07 : 56|8@1+ (1,0) [0|255] ""  PC

BO_ 2416176712 S2P_Cfg2__08: 8 SBMU
 SG_ S2P_Cfg2_SW_Ver_Byte9_08 : 0|8@1+ (1,0) [0|255] ""  PC
 SG_ S2P_Cfg2_SW_Ver_Byte10_08 : 8|8@1+ (1,0) [0|255] ""  PC
 SG_ S2P_Cfg2_SW_Ver_Byte11_08 : 16|8@1+ (1,0) [0|255] ""  PC
 SG_ S2P_Cfg2_SW_Ver_Byte12_08 : 24|8@1+ (1,0) [0|255] ""  PC
 SG_ S2P_Cfg2_SW_Ver_Byte13_08 : 32|8@1+ (1,0) [0|255] ""  PC
 SG_ S2P_Cfg2_SW_Ver_Byte14_08 : 40|8@1+ (1,0) [0|255] ""  PC
 SG_ S2P_Cfg2_SW_Ver_Byte15_08 : 48|8@1+ (1,0) [0|255] ""  PC
 SG_ S2P_Cfg2_SW_Ver_Byte16_08 : 56|8@1+ (1,0) [0|255] ""  PC

BO_ 2416176713 S2P_Cfg2__09: 8 SBMU
 SG_ S2P_Cfg2_SW_Ver_Byte9_09 : 0|8@1+ (1,0) [0|255] ""  PC
 SG_ S2P_Cfg2_SW_Ver_Byte10_09 : 8|8@1+ (1,0) [0|255] ""  PC
 SG_ S2P_Cfg2_SW_Ver_Byte11_09 : 16|8@1+ (1,0) [0|255] ""  PC
 SG_ S2P_Cfg2_SW_Ver_Byte12_09 : 24|8@1+ (1,0) [0|255] ""  PC
 SG_ S2P_Cfg2_SW_Ver_Byte13_09 : 32|8@1+ (1,0) [0|255] ""  PC
 SG_ S2P_Cfg2_SW_Ver_Byte14_09 : 40|8@1+ (1,0) [0|255] ""  PC
 SG_ S2P_Cfg2_SW_Ver_Byte15_09 : 48|8@1+ (1,0) [0|255] ""  PC
 SG_ S2P_Cfg2_SW_Ver_Byte16_09 : 56|8@1+ (1,0) [0|255] ""  PC

BO_ 2416176714 S2P_Cfg2__10: 8 SBMU
 SG_ S2P_Cfg2_SW_Ver_Byte9_10 : 0|8@1+ (1,0) [0|255] ""  PC
 SG_ S2P_Cfg2_SW_Ver_Byte10_10 : 8|8@1+ (1,0) [0|255] ""  PC
 SG_ S2P_Cfg2_SW_Ver_Byte11_10 : 16|8@1+ (1,0) [0|255] ""  PC
 SG_ S2P_Cfg2_SW_Ver_Byte12_10 : 24|8@1+ (1,0) [0|255] ""  PC
 SG_ S2P_Cfg2_SW_Ver_Byte13_10 : 32|8@1+ (1,0) [0|255] ""  PC
 SG_ S2P_Cfg2_SW_Ver_Byte14_10 : 40|8@1+ (1,0) [0|255] ""  PC
 SG_ S2P_Cfg2_SW_Ver_Byte15_10 : 48|8@1+ (1,0) [0|255] ""  PC
 SG_ S2P_Cfg2_SW_Ver_Byte16_10 : 56|8@1+ (1,0) [0|255] ""  PC

BO_ 2416176715 S2P_Cfg2__11: 8 SBMU
 SG_ S2P_Cfg2_SW_Ver_Byte9_11 : 0|8@1+ (1,0) [0|255] ""  PC
 SG_ S2P_Cfg2_SW_Ver_Byte10_11 : 8|8@1+ (1,0) [0|255] ""  PC
 SG_ S2P_Cfg2_SW_Ver_Byte11_11 : 16|8@1+ (1,0) [0|255] ""  PC
 SG_ S2P_Cfg2_SW_Ver_Byte12_11 : 24|8@1+ (1,0) [0|255] ""  PC
 SG_ S2P_Cfg2_SW_Ver_Byte13_11 : 32|8@1+ (1,0) [0|255] ""  PC
 SG_ S2P_Cfg2_SW_Ver_Byte14_11 : 40|8@1+ (1,0) [0|255] ""  PC
 SG_ S2P_Cfg2_SW_Ver_Byte15_11 : 48|8@1+ (1,0) [0|255] ""  PC
 SG_ S2P_Cfg2_SW_Ver_Byte16_11 : 56|8@1+ (1,0) [0|255] ""  PC

BO_ 2416176716 S2P_Cfg2__12: 8 SBMU
 SG_ S2P_Cfg2_SW_Ver_Byte9_12 : 0|8@1+ (1,0) [0|255] ""  PC
 SG_ S2P_Cfg2_SW_Ver_Byte10_12 : 8|8@1+ (1,0) [0|255] ""  PC
 SG_ S2P_Cfg2_SW_Ver_Byte11_12 : 16|8@1+ (1,0) [0|255] ""  PC
 SG_ S2P_Cfg2_SW_Ver_Byte12_12 : 24|8@1+ (1,0) [0|255] ""  PC
 SG_ S2P_Cfg2_SW_Ver_Byte13_12 : 32|8@1+ (1,0) [0|255] ""  PC
 SG_ S2P_Cfg2_SW_Ver_Byte14_12 : 40|8@1+ (1,0) [0|255] ""  PC
 SG_ S2P_Cfg2_SW_Ver_Byte15_12 : 48|8@1+ (1,0) [0|255] ""  PC
 SG_ S2P_Cfg2_SW_Ver_Byte16_12 : 56|8@1+ (1,0) [0|255] ""  PC

BO_ 2416176717 S2P_Cfg2__13: 8 SBMU
 SG_ S2P_Cfg2_SW_Ver_Byte9_13 : 0|8@1+ (1,0) [0|255] ""  PC
 SG_ S2P_Cfg2_SW_Ver_Byte10_13 : 8|8@1+ (1,0) [0|255] ""  PC
 SG_ S2P_Cfg2_SW_Ver_Byte11_13 : 16|8@1+ (1,0) [0|255] ""  PC
 SG_ S2P_Cfg2_SW_Ver_Byte12_13 : 24|8@1+ (1,0) [0|255] ""  PC
 SG_ S2P_Cfg2_SW_Ver_Byte13_13 : 32|8@1+ (1,0) [0|255] ""  PC
 SG_ S2P_Cfg2_SW_Ver_Byte14_13 : 40|8@1+ (1,0) [0|255] ""  PC
 SG_ S2P_Cfg2_SW_Ver_Byte15_13 : 48|8@1+ (1,0) [0|255] ""  PC
 SG_ S2P_Cfg2_SW_Ver_Byte16_13 : 56|8@1+ (1,0) [0|255] ""  PC

BO_ 2416176718 S2P_Cfg2__14: 8 SBMU
 SG_ S2P_Cfg2_SW_Ver_Byte9_14 : 0|8@1+ (1,0) [0|255] ""  PC
 SG_ S2P_Cfg2_SW_Ver_Byte10_14 : 8|8@1+ (1,0) [0|255] ""  PC
 SG_ S2P_Cfg2_SW_Ver_Byte11_14 : 16|8@1+ (1,0) [0|255] ""  PC
 SG_ S2P_Cfg2_SW_Ver_Byte12_14 : 24|8@1+ (1,0) [0|255] ""  PC
 SG_ S2P_Cfg2_SW_Ver_Byte13_14 : 32|8@1+ (1,0) [0|255] ""  PC
 SG_ S2P_Cfg2_SW_Ver_Byte14_14 : 40|8@1+ (1,0) [0|255] ""  PC
 SG_ S2P_Cfg2_SW_Ver_Byte15_14 : 48|8@1+ (1,0) [0|255] ""  PC
 SG_ S2P_Cfg2_SW_Ver_Byte16_14 : 56|8@1+ (1,0) [0|255] ""  PC

BO_ 2416176719 S2P_Cfg2__15: 8 SBMU
 SG_ S2P_Cfg2_SW_Ver_Byte9_15 : 0|8@1+ (1,0) [0|255] ""  PC
 SG_ S2P_Cfg2_SW_Ver_Byte10_15 : 8|8@1+ (1,0) [0|255] ""  PC
 SG_ S2P_Cfg2_SW_Ver_Byte11_15 : 16|8@1+ (1,0) [0|255] ""  PC
 SG_ S2P_Cfg2_SW_Ver_Byte12_15 : 24|8@1+ (1,0) [0|255] ""  PC
 SG_ S2P_Cfg2_SW_Ver_Byte13_15 : 32|8@1+ (1,0) [0|255] ""  PC
 SG_ S2P_Cfg2_SW_Ver_Byte14_15 : 40|8@1+ (1,0) [0|255] ""  PC
 SG_ S2P_Cfg2_SW_Ver_Byte15_15 : 48|8@1+ (1,0) [0|255] ""  PC
 SG_ S2P_Cfg2_SW_Ver_Byte16_15 : 56|8@1+ (1,0) [0|255] ""  PC

BO_ 2416176720 S2P_Cfg2__16: 8 SBMU
 SG_ S2P_Cfg2_SW_Ver_Byte9_16 : 0|8@1+ (1,0) [0|255] ""  PC
 SG_ S2P_Cfg2_SW_Ver_Byte10_16 : 8|8@1+ (1,0) [0|255] ""  PC
 SG_ S2P_Cfg2_SW_Ver_Byte11_16 : 16|8@1+ (1,0) [0|255] ""  PC
 SG_ S2P_Cfg2_SW_Ver_Byte12_16 : 24|8@1+ (1,0) [0|255] ""  PC
 SG_ S2P_Cfg2_SW_Ver_Byte13_16 : 32|8@1+ (1,0) [0|255] ""  PC
 SG_ S2P_Cfg2_SW_Ver_Byte14_16 : 40|8@1+ (1,0) [0|255] ""  PC
 SG_ S2P_Cfg2_SW_Ver_Byte15_16 : 48|8@1+ (1,0) [0|255] ""  PC
 SG_ S2P_Cfg2_SW_Ver_Byte16_16 : 56|8@1+ (1,0) [0|255] ""  PC

BO_ 2416176721 S2P_Cfg2__17: 8 SBMU
 SG_ S2P_Cfg2_SW_Ver_Byte9_17 : 0|8@1+ (1,0) [0|255] ""  PC
 SG_ S2P_Cfg2_SW_Ver_Byte10_17 : 8|8@1+ (1,0) [0|255] ""  PC
 SG_ S2P_Cfg2_SW_Ver_Byte11_17 : 16|8@1+ (1,0) [0|255] ""  PC
 SG_ S2P_Cfg2_SW_Ver_Byte12_17 : 24|8@1+ (1,0) [0|255] ""  PC
 SG_ S2P_Cfg2_SW_Ver_Byte13_17 : 32|8@1+ (1,0) [0|255] ""  PC
 SG_ S2P_Cfg2_SW_Ver_Byte14_17 : 40|8@1+ (1,0) [0|255] ""  PC
 SG_ S2P_Cfg2_SW_Ver_Byte15_17 : 48|8@1+ (1,0) [0|255] ""  PC
 SG_ S2P_Cfg2_SW_Ver_Byte16_17 : 56|8@1+ (1,0) [0|255] ""  PC

BO_ 2416176722 S2P_Cfg2__18: 8 SBMU
 SG_ S2P_Cfg2_SW_Ver_Byte9_18 : 0|8@1+ (1,0) [0|255] ""  PC
 SG_ S2P_Cfg2_SW_Ver_Byte10_18 : 8|8@1+ (1,0) [0|255] ""  PC
 SG_ S2P_Cfg2_SW_Ver_Byte11_18 : 16|8@1+ (1,0) [0|255] ""  PC
 SG_ S2P_Cfg2_SW_Ver_Byte12_18 : 24|8@1+ (1,0) [0|255] ""  PC
 SG_ S2P_Cfg2_SW_Ver_Byte13_18 : 32|8@1+ (1,0) [0|255] ""  PC
 SG_ S2P_Cfg2_SW_Ver_Byte14_18 : 40|8@1+ (1,0) [0|255] ""  PC
 SG_ S2P_Cfg2_SW_Ver_Byte15_18 : 48|8@1+ (1,0) [0|255] ""  PC
 SG_ S2P_Cfg2_SW_Ver_Byte16_18 : 56|8@1+ (1,0) [0|255] ""  PC

BO_ 2416176723 S2P_Cfg2__19: 8 SBMU
 SG_ S2P_Cfg2_SW_Ver_Byte9_19 : 0|8@1+ (1,0) [0|255] ""  PC
 SG_ S2P_Cfg2_SW_Ver_Byte10_19 : 8|8@1+ (1,0) [0|255] ""  PC
 SG_ S2P_Cfg2_SW_Ver_Byte11_19 : 16|8@1+ (1,0) [0|255] ""  PC
 SG_ S2P_Cfg2_SW_Ver_Byte12_19 : 24|8@1+ (1,0) [0|255] ""  PC
 SG_ S2P_Cfg2_SW_Ver_Byte13_19 : 32|8@1+ (1,0) [0|255] ""  PC
 SG_ S2P_Cfg2_SW_Ver_Byte14_19 : 40|8@1+ (1,0) [0|255] ""  PC
 SG_ S2P_Cfg2_SW_Ver_Byte15_19 : 48|8@1+ (1,0) [0|255] ""  PC
 SG_ S2P_Cfg2_SW_Ver_Byte16_19 : 56|8@1+ (1,0) [0|255] ""  PC

BO_ 2416176724 S2P_Cfg2__20: 8 SBMU
 SG_ S2P_Cfg2_SW_Ver_Byte9_20 : 0|8@1+ (1,0) [0|255] ""  PC
 SG_ S2P_Cfg2_SW_Ver_Byte10_20 : 8|8@1+ (1,0) [0|255] ""  PC
 SG_ S2P_Cfg2_SW_Ver_Byte11_20 : 16|8@1+ (1,0) [0|255] ""  PC
 SG_ S2P_Cfg2_SW_Ver_Byte12_20 : 24|8@1+ (1,0) [0|255] ""  PC
 SG_ S2P_Cfg2_SW_Ver_Byte13_20 : 32|8@1+ (1,0) [0|255] ""  PC
 SG_ S2P_Cfg2_SW_Ver_Byte14_20 : 40|8@1+ (1,0) [0|255] ""  PC
 SG_ S2P_Cfg2_SW_Ver_Byte15_20 : 48|8@1+ (1,0) [0|255] ""  PC
 SG_ S2P_Cfg2_SW_Ver_Byte16_20 : 56|8@1+ (1,0) [0|255] ""  PC

BO_ 2416176725 S2P_Cfg2__21: 8 SBMU
 SG_ S2P_Cfg2_SW_Ver_Byte9_21 : 0|8@1+ (1,0) [0|255] ""  PC
 SG_ S2P_Cfg2_SW_Ver_Byte10_21 : 8|8@1+ (1,0) [0|255] ""  PC
 SG_ S2P_Cfg2_SW_Ver_Byte11_21 : 16|8@1+ (1,0) [0|255] ""  PC
 SG_ S2P_Cfg2_SW_Ver_Byte12_21 : 24|8@1+ (1,0) [0|255] ""  PC
 SG_ S2P_Cfg2_SW_Ver_Byte13_21 : 32|8@1+ (1,0) [0|255] ""  PC
 SG_ S2P_Cfg2_SW_Ver_Byte14_21 : 40|8@1+ (1,0) [0|255] ""  PC
 SG_ S2P_Cfg2_SW_Ver_Byte15_21 : 48|8@1+ (1,0) [0|255] ""  PC
 SG_ S2P_Cfg2_SW_Ver_Byte16_21 : 56|8@1+ (1,0) [0|255] ""  PC

BO_ 2416176726 S2P_Cfg2__22: 8 SBMU
 SG_ S2P_Cfg2_SW_Ver_Byte9_22 : 0|8@1+ (1,0) [0|255] ""  PC
 SG_ S2P_Cfg2_SW_Ver_Byte10_22 : 8|8@1+ (1,0) [0|255] ""  PC
 SG_ S2P_Cfg2_SW_Ver_Byte11_22 : 16|8@1+ (1,0) [0|255] ""  PC
 SG_ S2P_Cfg2_SW_Ver_Byte12_22 : 24|8@1+ (1,0) [0|255] ""  PC
 SG_ S2P_Cfg2_SW_Ver_Byte13_22 : 32|8@1+ (1,0) [0|255] ""  PC
 SG_ S2P_Cfg2_SW_Ver_Byte14_22 : 40|8@1+ (1,0) [0|255] ""  PC
 SG_ S2P_Cfg2_SW_Ver_Byte15_22 : 48|8@1+ (1,0) [0|255] ""  PC
 SG_ S2P_Cfg2_SW_Ver_Byte16_22 : 56|8@1+ (1,0) [0|255] ""  PC

BO_ 2416176727 S2P_Cfg2__23: 8 SBMU
 SG_ S2P_Cfg2_SW_Ver_Byte9_23 : 0|8@1+ (1,0) [0|255] ""  PC
 SG_ S2P_Cfg2_SW_Ver_Byte10_23 : 8|8@1+ (1,0) [0|255] ""  PC
 SG_ S2P_Cfg2_SW_Ver_Byte11_23 : 16|8@1+ (1,0) [0|255] ""  PC
 SG_ S2P_Cfg2_SW_Ver_Byte12_23 : 24|8@1+ (1,0) [0|255] ""  PC
 SG_ S2P_Cfg2_SW_Ver_Byte13_23 : 32|8@1+ (1,0) [0|255] ""  PC
 SG_ S2P_Cfg2_SW_Ver_Byte14_23 : 40|8@1+ (1,0) [0|255] ""  PC
 SG_ S2P_Cfg2_SW_Ver_Byte15_23 : 48|8@1+ (1,0) [0|255] ""  PC
 SG_ S2P_Cfg2_SW_Ver_Byte16_23 : 56|8@1+ (1,0) [0|255] ""  PC

BO_ 2416176728 S2P_Cfg2__24: 8 SBMU
 SG_ S2P_Cfg2_SW_Ver_Byte9_24 : 0|8@1+ (1,0) [0|255] ""  PC
 SG_ S2P_Cfg2_SW_Ver_Byte10_24 : 8|8@1+ (1,0) [0|255] ""  PC
 SG_ S2P_Cfg2_SW_Ver_Byte11_24 : 16|8@1+ (1,0) [0|255] ""  PC
 SG_ S2P_Cfg2_SW_Ver_Byte12_24 : 24|8@1+ (1,0) [0|255] ""  PC
 SG_ S2P_Cfg2_SW_Ver_Byte13_24 : 32|8@1+ (1,0) [0|255] ""  PC
 SG_ S2P_Cfg2_SW_Ver_Byte14_24 : 40|8@1+ (1,0) [0|255] ""  PC
 SG_ S2P_Cfg2_SW_Ver_Byte15_24 : 48|8@1+ (1,0) [0|255] ""  PC
 SG_ S2P_Cfg2_SW_Ver_Byte16_24 : 56|8@1+ (1,0) [0|255] ""  PC

BO_ 2416176729 S2P_Cfg2__25: 8 SBMU
 SG_ S2P_Cfg2_SW_Ver_Byte9_25 : 0|8@1+ (1,0) [0|255] ""  PC
 SG_ S2P_Cfg2_SW_Ver_Byte10_25 : 8|8@1+ (1,0) [0|255] ""  PC
 SG_ S2P_Cfg2_SW_Ver_Byte11_25 : 16|8@1+ (1,0) [0|255] ""  PC
 SG_ S2P_Cfg2_SW_Ver_Byte12_25 : 24|8@1+ (1,0) [0|255] ""  PC
 SG_ S2P_Cfg2_SW_Ver_Byte13_25 : 32|8@1+ (1,0) [0|255] ""  PC
 SG_ S2P_Cfg2_SW_Ver_Byte14_25 : 40|8@1+ (1,0) [0|255] ""  PC
 SG_ S2P_Cfg2_SW_Ver_Byte15_25 : 48|8@1+ (1,0) [0|255] ""  PC
 SG_ S2P_Cfg2_SW_Ver_Byte16_25 : 56|8@1+ (1,0) [0|255] ""  PC

BO_ 2416176730 S2P_Cfg2__26: 8 SBMU
 SG_ S2P_Cfg2_SW_Ver_Byte9_26 : 0|8@1+ (1,0) [0|255] ""  PC
 SG_ S2P_Cfg2_SW_Ver_Byte10_26 : 8|8@1+ (1,0) [0|255] ""  PC
 SG_ S2P_Cfg2_SW_Ver_Byte11_26 : 16|8@1+ (1,0) [0|255] ""  PC
 SG_ S2P_Cfg2_SW_Ver_Byte12_26 : 24|8@1+ (1,0) [0|255] ""  PC
 SG_ S2P_Cfg2_SW_Ver_Byte13_26 : 32|8@1+ (1,0) [0|255] ""  PC
 SG_ S2P_Cfg2_SW_Ver_Byte14_26 : 40|8@1+ (1,0) [0|255] ""  PC
 SG_ S2P_Cfg2_SW_Ver_Byte15_26 : 48|8@1+ (1,0) [0|255] ""  PC
 SG_ S2P_Cfg2_SW_Ver_Byte16_26 : 56|8@1+ (1,0) [0|255] ""  PC

BO_ 2416176731 S2P_Cfg2__27: 8 SBMU
 SG_ S2P_Cfg2_SW_Ver_Byte9_27 : 0|8@1+ (1,0) [0|255] ""  PC
 SG_ S2P_Cfg2_SW_Ver_Byte10_27 : 8|8@1+ (1,0) [0|255] ""  PC
 SG_ S2P_Cfg2_SW_Ver_Byte11_27 : 16|8@1+ (1,0) [0|255] ""  PC
 SG_ S2P_Cfg2_SW_Ver_Byte12_27 : 24|8@1+ (1,0) [0|255] ""  PC
 SG_ S2P_Cfg2_SW_Ver_Byte13_27 : 32|8@1+ (1,0) [0|255] ""  PC
 SG_ S2P_Cfg2_SW_Ver_Byte14_27 : 40|8@1+ (1,0) [0|255] ""  PC
 SG_ S2P_Cfg2_SW_Ver_Byte15_27 : 48|8@1+ (1,0) [0|255] ""  PC
 SG_ S2P_Cfg2_SW_Ver_Byte16_27 : 56|8@1+ (1,0) [0|255] ""  PC

BO_ 2416176732 S2P_Cfg2__28: 8 SBMU
 SG_ S2P_Cfg2_SW_Ver_Byte9_28 : 0|8@1+ (1,0) [0|255] ""  PC
 SG_ S2P_Cfg2_SW_Ver_Byte10_28 : 8|8@1+ (1,0) [0|255] ""  PC
 SG_ S2P_Cfg2_SW_Ver_Byte11_28 : 16|8@1+ (1,0) [0|255] ""  PC
 SG_ S2P_Cfg2_SW_Ver_Byte12_28 : 24|8@1+ (1,0) [0|255] ""  PC
 SG_ S2P_Cfg2_SW_Ver_Byte13_28 : 32|8@1+ (1,0) [0|255] ""  PC
 SG_ S2P_Cfg2_SW_Ver_Byte14_28 : 40|8@1+ (1,0) [0|255] ""  PC
 SG_ S2P_Cfg2_SW_Ver_Byte15_28 : 48|8@1+ (1,0) [0|255] ""  PC
 SG_ S2P_Cfg2_SW_Ver_Byte16_28 : 56|8@1+ (1,0) [0|255] ""  PC

BO_ 2416176733 S2P_Cfg2__29: 8 SBMU
 SG_ S2P_Cfg2_SW_Ver_Byte9_29 : 0|8@1+ (1,0) [0|255] ""  PC
 SG_ S2P_Cfg2_SW_Ver_Byte10_29 : 8|8@1+ (1,0) [0|255] ""  PC
 SG_ S2P_Cfg2_SW_Ver_Byte11_29 : 16|8@1+ (1,0) [0|255] ""  PC
 SG_ S2P_Cfg2_SW_Ver_Byte12_29 : 24|8@1+ (1,0) [0|255] ""  PC
 SG_ S2P_Cfg2_SW_Ver_Byte13_29 : 32|8@1+ (1,0) [0|255] ""  PC
 SG_ S2P_Cfg2_SW_Ver_Byte14_29 : 40|8@1+ (1,0) [0|255] ""  PC
 SG_ S2P_Cfg2_SW_Ver_Byte15_29 : 48|8@1+ (1,0) [0|255] ""  PC
 SG_ S2P_Cfg2_SW_Ver_Byte16_29 : 56|8@1+ (1,0) [0|255] ""  PC

BO_ 2416176734 S2P_Cfg2__30: 8 SBMU
 SG_ S2P_Cfg2_SW_Ver_Byte9_30 : 0|8@1+ (1,0) [0|255] ""  PC
 SG_ S2P_Cfg2_SW_Ver_Byte10_30 : 8|8@1+ (1,0) [0|255] ""  PC
 SG_ S2P_Cfg2_SW_Ver_Byte11_30 : 16|8@1+ (1,0) [0|255] ""  PC
 SG_ S2P_Cfg2_SW_Ver_Byte12_30 : 24|8@1+ (1,0) [0|255] ""  PC
 SG_ S2P_Cfg2_SW_Ver_Byte13_30 : 32|8@1+ (1,0) [0|255] ""  PC
 SG_ S2P_Cfg2_SW_Ver_Byte14_30 : 40|8@1+ (1,0) [0|255] ""  PC
 SG_ S2P_Cfg2_SW_Ver_Byte15_30 : 48|8@1+ (1,0) [0|255] ""  PC
 SG_ S2P_Cfg2_SW_Ver_Byte16_30 : 56|8@1+ (1,0) [0|255] ""  PC

BO_ 2416176735 S2P_Cfg2__31: 8 SBMU
 SG_ S2P_Cfg2_SW_Ver_Byte9_31 : 0|8@1+ (1,0) [0|255] ""  PC
 SG_ S2P_Cfg2_SW_Ver_Byte10_31 : 8|8@1+ (1,0) [0|255] ""  PC
 SG_ S2P_Cfg2_SW_Ver_Byte11_31 : 16|8@1+ (1,0) [0|255] ""  PC
 SG_ S2P_Cfg2_SW_Ver_Byte12_31 : 24|8@1+ (1,0) [0|255] ""  PC
 SG_ S2P_Cfg2_SW_Ver_Byte13_31 : 32|8@1+ (1,0) [0|255] ""  PC
 SG_ S2P_Cfg2_SW_Ver_Byte14_31 : 40|8@1+ (1,0) [0|255] ""  PC
 SG_ S2P_Cfg2_SW_Ver_Byte15_31 : 48|8@1+ (1,0) [0|255] ""  PC
 SG_ S2P_Cfg2_SW_Ver_Byte16_31 : 56|8@1+ (1,0) [0|255] ""  PC

BO_ 2416176736 S2P_Cfg2__32: 8 SBMU
 SG_ S2P_Cfg2_SW_Ver_Byte9_32 : 0|8@1+ (1,0) [0|255] ""  PC
 SG_ S2P_Cfg2_SW_Ver_Byte10_32 : 8|8@1+ (1,0) [0|255] ""  PC
 SG_ S2P_Cfg2_SW_Ver_Byte11_32 : 16|8@1+ (1,0) [0|255] ""  PC
 SG_ S2P_Cfg2_SW_Ver_Byte12_32 : 24|8@1+ (1,0) [0|255] ""  PC
 SG_ S2P_Cfg2_SW_Ver_Byte13_32 : 32|8@1+ (1,0) [0|255] ""  PC
 SG_ S2P_Cfg2_SW_Ver_Byte14_32 : 40|8@1+ (1,0) [0|255] ""  PC
 SG_ S2P_Cfg2_SW_Ver_Byte15_32 : 48|8@1+ (1,0) [0|255] ""  PC
 SG_ S2P_Cfg2_SW_Ver_Byte16_32 : 56|8@1+ (1,0) [0|255] ""  PC

BO_ 2416176737 S2P_Cfg2__33: 8 SBMU
 SG_ S2P_Cfg2_SW_Ver_Byte9_33 : 0|8@1+ (1,0) [0|255] ""  PC
 SG_ S2P_Cfg2_SW_Ver_Byte10_33 : 8|8@1+ (1,0) [0|255] ""  PC
 SG_ S2P_Cfg2_SW_Ver_Byte11_33 : 16|8@1+ (1,0) [0|255] ""  PC
 SG_ S2P_Cfg2_SW_Ver_Byte12_33 : 24|8@1+ (1,0) [0|255] ""  PC
 SG_ S2P_Cfg2_SW_Ver_Byte13_33 : 32|8@1+ (1,0) [0|255] ""  PC
 SG_ S2P_Cfg2_SW_Ver_Byte14_33 : 40|8@1+ (1,0) [0|255] ""  PC
 SG_ S2P_Cfg2_SW_Ver_Byte15_33 : 48|8@1+ (1,0) [0|255] ""  PC
 SG_ S2P_Cfg2_SW_Ver_Byte16_33 : 56|8@1+ (1,0) [0|255] ""  PC

BO_ 2416176738 S2P_Cfg2__34: 8 SBMU
 SG_ S2P_Cfg2_SW_Ver_Byte9_34 : 0|8@1+ (1,0) [0|255] ""  PC
 SG_ S2P_Cfg2_SW_Ver_Byte10_34 : 8|8@1+ (1,0) [0|255] ""  PC
 SG_ S2P_Cfg2_SW_Ver_Byte11_34 : 16|8@1+ (1,0) [0|255] ""  PC
 SG_ S2P_Cfg2_SW_Ver_Byte12_34 : 24|8@1+ (1,0) [0|255] ""  PC
 SG_ S2P_Cfg2_SW_Ver_Byte13_34 : 32|8@1+ (1,0) [0|255] ""  PC
 SG_ S2P_Cfg2_SW_Ver_Byte14_34 : 40|8@1+ (1,0) [0|255] ""  PC
 SG_ S2P_Cfg2_SW_Ver_Byte15_34 : 48|8@1+ (1,0) [0|255] ""  PC
 SG_ S2P_Cfg2_SW_Ver_Byte16_34 : 56|8@1+ (1,0) [0|255] ""  PC

BO_ 2416176739 S2P_Cfg2__35: 8 SBMU
 SG_ S2P_Cfg2_SW_Ver_Byte9_35 : 0|8@1+ (1,0) [0|255] ""  PC
 SG_ S2P_Cfg2_SW_Ver_Byte10_35 : 8|8@1+ (1,0) [0|255] ""  PC
 SG_ S2P_Cfg2_SW_Ver_Byte11_35 : 16|8@1+ (1,0) [0|255] ""  PC
 SG_ S2P_Cfg2_SW_Ver_Byte12_35 : 24|8@1+ (1,0) [0|255] ""  PC
 SG_ S2P_Cfg2_SW_Ver_Byte13_35 : 32|8@1+ (1,0) [0|255] ""  PC
 SG_ S2P_Cfg2_SW_Ver_Byte14_35 : 40|8@1+ (1,0) [0|255] ""  PC
 SG_ S2P_Cfg2_SW_Ver_Byte15_35 : 48|8@1+ (1,0) [0|255] ""  PC
 SG_ S2P_Cfg2_SW_Ver_Byte16_35 : 56|8@1+ (1,0) [0|255] ""  PC

BO_ 2416176740 S2P_Cfg2__36: 8 SBMU
 SG_ S2P_Cfg2_SW_Ver_Byte9_36 : 0|8@1+ (1,0) [0|255] ""  PC
 SG_ S2P_Cfg2_SW_Ver_Byte10_36 : 8|8@1+ (1,0) [0|255] ""  PC
 SG_ S2P_Cfg2_SW_Ver_Byte11_36 : 16|8@1+ (1,0) [0|255] ""  PC
 SG_ S2P_Cfg2_SW_Ver_Byte12_36 : 24|8@1+ (1,0) [0|255] ""  PC
 SG_ S2P_Cfg2_SW_Ver_Byte13_36 : 32|8@1+ (1,0) [0|255] ""  PC
 SG_ S2P_Cfg2_SW_Ver_Byte14_36 : 40|8@1+ (1,0) [0|255] ""  PC
 SG_ S2P_Cfg2_SW_Ver_Byte15_36 : 48|8@1+ (1,0) [0|255] ""  PC
 SG_ S2P_Cfg2_SW_Ver_Byte16_36 : 56|8@1+ (1,0) [0|255] ""  PC

BO_ 2416176741 S2P_Cfg2__37: 8 SBMU
 SG_ S2P_Cfg2_SW_Ver_Byte9_37 : 0|8@1+ (1,0) [0|255] ""  PC
 SG_ S2P_Cfg2_SW_Ver_Byte10_37 : 8|8@1+ (1,0) [0|255] ""  PC
 SG_ S2P_Cfg2_SW_Ver_Byte11_37 : 16|8@1+ (1,0) [0|255] ""  PC
 SG_ S2P_Cfg2_SW_Ver_Byte12_37 : 24|8@1+ (1,0) [0|255] ""  PC
 SG_ S2P_Cfg2_SW_Ver_Byte13_37 : 32|8@1+ (1,0) [0|255] ""  PC
 SG_ S2P_Cfg2_SW_Ver_Byte14_37 : 40|8@1+ (1,0) [0|255] ""  PC
 SG_ S2P_Cfg2_SW_Ver_Byte15_37 : 48|8@1+ (1,0) [0|255] ""  PC
 SG_ S2P_Cfg2_SW_Ver_Byte16_37 : 56|8@1+ (1,0) [0|255] ""  PC

BO_ 2416176742 S2P_Cfg2__38: 8 SBMU
 SG_ S2P_Cfg2_SW_Ver_Byte9_38 : 0|8@1+ (1,0) [0|255] ""  PC
 SG_ S2P_Cfg2_SW_Ver_Byte10_38 : 8|8@1+ (1,0) [0|255] ""  PC
 SG_ S2P_Cfg2_SW_Ver_Byte11_38 : 16|8@1+ (1,0) [0|255] ""  PC
 SG_ S2P_Cfg2_SW_Ver_Byte12_38 : 24|8@1+ (1,0) [0|255] ""  PC
 SG_ S2P_Cfg2_SW_Ver_Byte13_38 : 32|8@1+ (1,0) [0|255] ""  PC
 SG_ S2P_Cfg2_SW_Ver_Byte14_38 : 40|8@1+ (1,0) [0|255] ""  PC
 SG_ S2P_Cfg2_SW_Ver_Byte15_38 : 48|8@1+ (1,0) [0|255] ""  PC
 SG_ S2P_Cfg2_SW_Ver_Byte16_38 : 56|8@1+ (1,0) [0|255] ""  PC

BO_ 2416176743 S2P_Cfg2__39: 8 SBMU
 SG_ S2P_Cfg2_SW_Ver_Byte9_39 : 0|8@1+ (1,0) [0|255] ""  PC
 SG_ S2P_Cfg2_SW_Ver_Byte10_39 : 8|8@1+ (1,0) [0|255] ""  PC
 SG_ S2P_Cfg2_SW_Ver_Byte11_39 : 16|8@1+ (1,0) [0|255] ""  PC
 SG_ S2P_Cfg2_SW_Ver_Byte12_39 : 24|8@1+ (1,0) [0|255] ""  PC
 SG_ S2P_Cfg2_SW_Ver_Byte13_39 : 32|8@1+ (1,0) [0|255] ""  PC
 SG_ S2P_Cfg2_SW_Ver_Byte14_39 : 40|8@1+ (1,0) [0|255] ""  PC
 SG_ S2P_Cfg2_SW_Ver_Byte15_39 : 48|8@1+ (1,0) [0|255] ""  PC
 SG_ S2P_Cfg2_SW_Ver_Byte16_39 : 56|8@1+ (1,0) [0|255] ""  PC

BO_ 2416176744 S2P_Cfg2__40: 8 SBMU
 SG_ S2P_Cfg2_SW_Ver_Byte9_40 : 0|8@1+ (1,0) [0|255] ""  PC
 SG_ S2P_Cfg2_SW_Ver_Byte10_40 : 8|8@1+ (1,0) [0|255] ""  PC
 SG_ S2P_Cfg2_SW_Ver_Byte11_40 : 16|8@1+ (1,0) [0|255] ""  PC
 SG_ S2P_Cfg2_SW_Ver_Byte12_40 : 24|8@1+ (1,0) [0|255] ""  PC
 SG_ S2P_Cfg2_SW_Ver_Byte13_40 : 32|8@1+ (1,0) [0|255] ""  PC
 SG_ S2P_Cfg2_SW_Ver_Byte14_40 : 40|8@1+ (1,0) [0|255] ""  PC
 SG_ S2P_Cfg2_SW_Ver_Byte15_40 : 48|8@1+ (1,0) [0|255] ""  PC
 SG_ S2P_Cfg2_SW_Ver_Byte16_40 : 56|8@1+ (1,0) [0|255] ""  PC

BO_ 2416176745 S2P_Cfg2__41: 8 SBMU
 SG_ S2P_Cfg2_SW_Ver_Byte9_41 : 0|8@1+ (1,0) [0|255] ""  PC
 SG_ S2P_Cfg2_SW_Ver_Byte10_41 : 8|8@1+ (1,0) [0|255] ""  PC
 SG_ S2P_Cfg2_SW_Ver_Byte11_41 : 16|8@1+ (1,0) [0|255] ""  PC
 SG_ S2P_Cfg2_SW_Ver_Byte12_41 : 24|8@1+ (1,0) [0|255] ""  PC
 SG_ S2P_Cfg2_SW_Ver_Byte13_41 : 32|8@1+ (1,0) [0|255] ""  PC
 SG_ S2P_Cfg2_SW_Ver_Byte14_41 : 40|8@1+ (1,0) [0|255] ""  PC
 SG_ S2P_Cfg2_SW_Ver_Byte15_41 : 48|8@1+ (1,0) [0|255] ""  PC
 SG_ S2P_Cfg2_SW_Ver_Byte16_41 : 56|8@1+ (1,0) [0|255] ""  PC

BO_ 2416176746 S2P_Cfg2__42: 8 SBMU
 SG_ S2P_Cfg2_SW_Ver_Byte9_42 : 0|8@1+ (1,0) [0|255] ""  PC
 SG_ S2P_Cfg2_SW_Ver_Byte10_42 : 8|8@1+ (1,0) [0|255] ""  PC
 SG_ S2P_Cfg2_SW_Ver_Byte11_42 : 16|8@1+ (1,0) [0|255] ""  PC
 SG_ S2P_Cfg2_SW_Ver_Byte12_42 : 24|8@1+ (1,0) [0|255] ""  PC
 SG_ S2P_Cfg2_SW_Ver_Byte13_42 : 32|8@1+ (1,0) [0|255] ""  PC
 SG_ S2P_Cfg2_SW_Ver_Byte14_42 : 40|8@1+ (1,0) [0|255] ""  PC
 SG_ S2P_Cfg2_SW_Ver_Byte15_42 : 48|8@1+ (1,0) [0|255] ""  PC
 SG_ S2P_Cfg2_SW_Ver_Byte16_42 : 56|8@1+ (1,0) [0|255] ""  PC

BO_ 2416176747 S2P_Cfg2__43: 8 SBMU
 SG_ S2P_Cfg2_SW_Ver_Byte9_43 : 0|8@1+ (1,0) [0|255] ""  PC
 SG_ S2P_Cfg2_SW_Ver_Byte10_43 : 8|8@1+ (1,0) [0|255] ""  PC
 SG_ S2P_Cfg2_SW_Ver_Byte11_43 : 16|8@1+ (1,0) [0|255] ""  PC
 SG_ S2P_Cfg2_SW_Ver_Byte12_43 : 24|8@1+ (1,0) [0|255] ""  PC
 SG_ S2P_Cfg2_SW_Ver_Byte13_43 : 32|8@1+ (1,0) [0|255] ""  PC
 SG_ S2P_Cfg2_SW_Ver_Byte14_43 : 40|8@1+ (1,0) [0|255] ""  PC
 SG_ S2P_Cfg2_SW_Ver_Byte15_43 : 48|8@1+ (1,0) [0|255] ""  PC
 SG_ S2P_Cfg2_SW_Ver_Byte16_43 : 56|8@1+ (1,0) [0|255] ""  PC

BO_ 2416176748 S2P_Cfg2__44: 8 SBMU
 SG_ S2P_Cfg2_SW_Ver_Byte9_44 : 0|8@1+ (1,0) [0|255] ""  PC
 SG_ S2P_Cfg2_SW_Ver_Byte10_44 : 8|8@1+ (1,0) [0|255] ""  PC
 SG_ S2P_Cfg2_SW_Ver_Byte11_44 : 16|8@1+ (1,0) [0|255] ""  PC
 SG_ S2P_Cfg2_SW_Ver_Byte12_44 : 24|8@1+ (1,0) [0|255] ""  PC
 SG_ S2P_Cfg2_SW_Ver_Byte13_44 : 32|8@1+ (1,0) [0|255] ""  PC
 SG_ S2P_Cfg2_SW_Ver_Byte14_44 : 40|8@1+ (1,0) [0|255] ""  PC
 SG_ S2P_Cfg2_SW_Ver_Byte15_44 : 48|8@1+ (1,0) [0|255] ""  PC
 SG_ S2P_Cfg2_SW_Ver_Byte16_44 : 56|8@1+ (1,0) [0|255] ""  PC

BO_ 2416176749 S2P_Cfg2__45: 8 SBMU
 SG_ S2P_Cfg2_SW_Ver_Byte9_45 : 0|8@1+ (1,0) [0|255] ""  PC
 SG_ S2P_Cfg2_SW_Ver_Byte10_45 : 8|8@1+ (1,0) [0|255] ""  PC
 SG_ S2P_Cfg2_SW_Ver_Byte11_45 : 16|8@1+ (1,0) [0|255] ""  PC
 SG_ S2P_Cfg2_SW_Ver_Byte12_45 : 24|8@1+ (1,0) [0|255] ""  PC
 SG_ S2P_Cfg2_SW_Ver_Byte13_45 : 32|8@1+ (1,0) [0|255] ""  PC
 SG_ S2P_Cfg2_SW_Ver_Byte14_45 : 40|8@1+ (1,0) [0|255] ""  PC
 SG_ S2P_Cfg2_SW_Ver_Byte15_45 : 48|8@1+ (1,0) [0|255] ""  PC
 SG_ S2P_Cfg2_SW_Ver_Byte16_45 : 56|8@1+ (1,0) [0|255] ""  PC

CM_ SG_ 2416045637 S2P_DIAG_BYTE1_05 "SBMU发送到PC的诊断报文（详见SBMU MCAN调试协议）";
CM_ SG_ 2416045637 S2P_DIAG_BYTE2_05 "SBMU发送到PC的诊断报文（详见SBMU MCAN调试协议）";
CM_ SG_ 2416045637 S2P_DIAG_BYTE3_05 "SBMU发送到PC的诊断报文（详见SBMU MCAN调试协议）";
CM_ SG_ 2416045637 S2P_DIAG_BYTE4_05 "SBMU发送到PC的诊断报文（详见SBMU MCAN调试协议）";
CM_ SG_ 2416045637 S2P_DIAG_BYTE5_05 "SBMU发送到PC的诊断报文（详见SBMU MCAN调试协议）";
CM_ SG_ 2416045637 S2P_DIAG_BYTE6_05 "SBMU发送到PC的诊断报文（详见SBMU MCAN调试协议）";
CM_ SG_ 2416045637 S2P_DIAG_BYTE7_05 "SBMU发送到PC的诊断报文（详见SBMU MCAN调试协议）";
CM_ SG_ 2416045637 S2P_DIAG_BYTE8_05 "SBMU发送到PC的诊断报文（详见SBMU MCAN调试协议）";
CM_ SG_ 2416045638 S2P_DIAG_BYTE1_06 "SBMU发送到PC的诊断报文（详见SBMU MCAN调试协议）";
CM_ SG_ 2416045638 S2P_DIAG_BYTE2_06 "SBMU发送到PC的诊断报文（详见SBMU MCAN调试协议）";
CM_ SG_ 2416045638 S2P_DIAG_BYTE3_06 "SBMU发送到PC的诊断报文（详见SBMU MCAN调试协议）";
CM_ SG_ 2416045638 S2P_DIAG_BYTE4_06 "SBMU发送到PC的诊断报文（详见SBMU MCAN调试协议）";
CM_ SG_ 2416045638 S2P_DIAG_BYTE5_06 "SBMU发送到PC的诊断报文（详见SBMU MCAN调试协议）";
CM_ SG_ 2416045638 S2P_DIAG_BYTE6_06 "SBMU发送到PC的诊断报文（详见SBMU MCAN调试协议）";
CM_ SG_ 2416045638 S2P_DIAG_BYTE7_06 "SBMU发送到PC的诊断报文（详见SBMU MCAN调试协议）";
CM_ SG_ 2416045638 S2P_DIAG_BYTE8_06 "SBMU发送到PC的诊断报文（详见SBMU MCAN调试协议）";
CM_ SG_ 2416045639 S2P_DIAG_BYTE1_07 "SBMU发送到PC的诊断报文（详见SBMU MCAN调试协议）";
CM_ SG_ 2416045639 S2P_DIAG_BYTE2_07 "SBMU发送到PC的诊断报文（详见SBMU MCAN调试协议）";
CM_ SG_ 2416045639 S2P_DIAG_BYTE3_07 "SBMU发送到PC的诊断报文（详见SBMU MCAN调试协议）";
CM_ SG_ 2416045639 S2P_DIAG_BYTE4_07 "SBMU发送到PC的诊断报文（详见SBMU MCAN调试协议）";
CM_ SG_ 2416045639 S2P_DIAG_BYTE5_07 "SBMU发送到PC的诊断报文（详见SBMU MCAN调试协议）";
CM_ SG_ 2416045639 S2P_DIAG_BYTE6_07 "SBMU发送到PC的诊断报文（详见SBMU MCAN调试协议）";
CM_ SG_ 2416045639 S2P_DIAG_BYTE7_07 "SBMU发送到PC的诊断报文（详见SBMU MCAN调试协议）";
CM_ SG_ 2416045639 S2P_DIAG_BYTE8_07 "SBMU发送到PC的诊断报文（详见SBMU MCAN调试协议）";
CM_ SG_ 2416045640 S2P_DIAG_BYTE1_08 "SBMU发送到PC的诊断报文（详见SBMU MCAN调试协议）";
CM_ SG_ 2416045640 S2P_DIAG_BYTE2_08 "SBMU发送到PC的诊断报文（详见SBMU MCAN调试协议）";
CM_ SG_ 2416045640 S2P_DIAG_BYTE3_08 "SBMU发送到PC的诊断报文（详见SBMU MCAN调试协议）";
CM_ SG_ 2416045640 S2P_DIAG_BYTE4_08 "SBMU发送到PC的诊断报文（详见SBMU MCAN调试协议）";
CM_ SG_ 2416045640 S2P_DIAG_BYTE5_08 "SBMU发送到PC的诊断报文（详见SBMU MCAN调试协议）";
CM_ SG_ 2416045640 S2P_DIAG_BYTE6_08 "SBMU发送到PC的诊断报文（详见SBMU MCAN调试协议）";
CM_ SG_ 2416045640 S2P_DIAG_BYTE7_08 "SBMU发送到PC的诊断报文（详见SBMU MCAN调试协议）";
CM_ SG_ 2416045640 S2P_DIAG_BYTE8_08 "SBMU发送到PC的诊断报文（详见SBMU MCAN调试协议）";
CM_ SG_ 2416045641 S2P_DIAG_BYTE1_09 "SBMU发送到PC的诊断报文（详见SBMU MCAN调试协议）";
CM_ SG_ 2416045641 S2P_DIAG_BYTE2_09 "SBMU发送到PC的诊断报文（详见SBMU MCAN调试协议）";
CM_ SG_ 2416045641 S2P_DIAG_BYTE3_09 "SBMU发送到PC的诊断报文（详见SBMU MCAN调试协议）";
CM_ SG_ 2416045641 S2P_DIAG_BYTE4_09 "SBMU发送到PC的诊断报文（详见SBMU MCAN调试协议）";
CM_ SG_ 2416045641 S2P_DIAG_BYTE5_09 "SBMU发送到PC的诊断报文（详见SBMU MCAN调试协议）";
CM_ SG_ 2416045641 S2P_DIAG_BYTE6_09 "SBMU发送到PC的诊断报文（详见SBMU MCAN调试协议）";
CM_ SG_ 2416045641 S2P_DIAG_BYTE7_09 "SBMU发送到PC的诊断报文（详见SBMU MCAN调试协议）";
CM_ SG_ 2416045641 S2P_DIAG_BYTE8_09 "SBMU发送到PC的诊断报文（详见SBMU MCAN调试协议）";
CM_ SG_ 2416045642 S2P_DIAG_BYTE1_10 "SBMU发送到PC的诊断报文（详见SBMU MCAN调试协议）";
CM_ SG_ 2416045642 S2P_DIAG_BYTE2_10 "SBMU发送到PC的诊断报文（详见SBMU MCAN调试协议）";
CM_ SG_ 2416045642 S2P_DIAG_BYTE3_10 "SBMU发送到PC的诊断报文（详见SBMU MCAN调试协议）";
CM_ SG_ 2416045642 S2P_DIAG_BYTE4_10 "SBMU发送到PC的诊断报文（详见SBMU MCAN调试协议）";
CM_ SG_ 2416045642 S2P_DIAG_BYTE5_10 "SBMU发送到PC的诊断报文（详见SBMU MCAN调试协议）";
CM_ SG_ 2416045642 S2P_DIAG_BYTE6_10 "SBMU发送到PC的诊断报文（详见SBMU MCAN调试协议）";
CM_ SG_ 2416045642 S2P_DIAG_BYTE7_10 "SBMU发送到PC的诊断报文（详见SBMU MCAN调试协议）";
CM_ SG_ 2416045642 S2P_DIAG_BYTE8_10 "SBMU发送到PC的诊断报文（详见SBMU MCAN调试协议）";
CM_ SG_ 2416045643 S2P_DIAG_BYTE1_11 "SBMU发送到PC的诊断报文（详见SBMU MCAN调试协议）";
CM_ SG_ 2416045643 S2P_DIAG_BYTE2_11 "SBMU发送到PC的诊断报文（详见SBMU MCAN调试协议）";
CM_ SG_ 2416045643 S2P_DIAG_BYTE3_11 "SBMU发送到PC的诊断报文（详见SBMU MCAN调试协议）";
CM_ SG_ 2416045643 S2P_DIAG_BYTE4_11 "SBMU发送到PC的诊断报文（详见SBMU MCAN调试协议）";
CM_ SG_ 2416045643 S2P_DIAG_BYTE5_11 "SBMU发送到PC的诊断报文（详见SBMU MCAN调试协议）";
CM_ SG_ 2416045643 S2P_DIAG_BYTE6_11 "SBMU发送到PC的诊断报文（详见SBMU MCAN调试协议）";
CM_ SG_ 2416045643 S2P_DIAG_BYTE7_11 "SBMU发送到PC的诊断报文（详见SBMU MCAN调试协议）";
CM_ SG_ 2416045643 S2P_DIAG_BYTE8_11 "SBMU发送到PC的诊断报文（详见SBMU MCAN调试协议）";
CM_ SG_ 2416045644 S2P_DIAG_BYTE1_12 "SBMU发送到PC的诊断报文（详见SBMU MCAN调试协议）";
CM_ SG_ 2416045644 S2P_DIAG_BYTE2_12 "SBMU发送到PC的诊断报文（详见SBMU MCAN调试协议）";
CM_ SG_ 2416045644 S2P_DIAG_BYTE3_12 "SBMU发送到PC的诊断报文（详见SBMU MCAN调试协议）";
CM_ SG_ 2416045644 S2P_DIAG_BYTE4_12 "SBMU发送到PC的诊断报文（详见SBMU MCAN调试协议）";
CM_ SG_ 2416045644 S2P_DIAG_BYTE5_12 "SBMU发送到PC的诊断报文（详见SBMU MCAN调试协议）";
CM_ SG_ 2416045644 S2P_DIAG_BYTE6_12 "SBMU发送到PC的诊断报文（详见SBMU MCAN调试协议）";
CM_ SG_ 2416045644 S2P_DIAG_BYTE7_12 "SBMU发送到PC的诊断报文（详见SBMU MCAN调试协议）";
CM_ SG_ 2416045644 S2P_DIAG_BYTE8_12 "SBMU发送到PC的诊断报文（详见SBMU MCAN调试协议）";
CM_ SG_ 2416045645 S2P_DIAG_BYTE1_13 "SBMU发送到PC的诊断报文（详见SBMU MCAN调试协议）";
CM_ SG_ 2416045645 S2P_DIAG_BYTE2_13 "SBMU发送到PC的诊断报文（详见SBMU MCAN调试协议）";
CM_ SG_ 2416045645 S2P_DIAG_BYTE3_13 "SBMU发送到PC的诊断报文（详见SBMU MCAN调试协议）";
CM_ SG_ 2416045645 S2P_DIAG_BYTE4_13 "SBMU发送到PC的诊断报文（详见SBMU MCAN调试协议）";
CM_ SG_ 2416045645 S2P_DIAG_BYTE5_13 "SBMU发送到PC的诊断报文（详见SBMU MCAN调试协议）";
CM_ SG_ 2416045645 S2P_DIAG_BYTE6_13 "SBMU发送到PC的诊断报文（详见SBMU MCAN调试协议）";
CM_ SG_ 2416045645 S2P_DIAG_BYTE7_13 "SBMU发送到PC的诊断报文（详见SBMU MCAN调试协议）";
CM_ SG_ 2416045645 S2P_DIAG_BYTE8_13 "SBMU发送到PC的诊断报文（详见SBMU MCAN调试协议）";
CM_ SG_ 2416045646 S2P_DIAG_BYTE1_14 "SBMU发送到PC的诊断报文（详见SBMU MCAN调试协议）";
CM_ SG_ 2416045646 S2P_DIAG_BYTE2_14 "SBMU发送到PC的诊断报文（详见SBMU MCAN调试协议）";
CM_ SG_ 2416045646 S2P_DIAG_BYTE3_14 "SBMU发送到PC的诊断报文（详见SBMU MCAN调试协议）";
CM_ SG_ 2416045646 S2P_DIAG_BYTE4_14 "SBMU发送到PC的诊断报文（详见SBMU MCAN调试协议）";
CM_ SG_ 2416045646 S2P_DIAG_BYTE5_14 "SBMU发送到PC的诊断报文（详见SBMU MCAN调试协议）";
CM_ SG_ 2416045646 S2P_DIAG_BYTE6_14 "SBMU发送到PC的诊断报文（详见SBMU MCAN调试协议）";
CM_ SG_ 2416045646 S2P_DIAG_BYTE7_14 "SBMU发送到PC的诊断报文（详见SBMU MCAN调试协议）";
CM_ SG_ 2416045646 S2P_DIAG_BYTE8_14 "SBMU发送到PC的诊断报文（详见SBMU MCAN调试协议）";
CM_ SG_ 2416045647 S2P_DIAG_BYTE1_15 "SBMU发送到PC的诊断报文（详见SBMU MCAN调试协议）";
CM_ SG_ 2416045647 S2P_DIAG_BYTE2_15 "SBMU发送到PC的诊断报文（详见SBMU MCAN调试协议）";
CM_ SG_ 2416045647 S2P_DIAG_BYTE3_15 "SBMU发送到PC的诊断报文（详见SBMU MCAN调试协议）";
CM_ SG_ 2416045647 S2P_DIAG_BYTE4_15 "SBMU发送到PC的诊断报文（详见SBMU MCAN调试协议）";
CM_ SG_ 2416045647 S2P_DIAG_BYTE5_15 "SBMU发送到PC的诊断报文（详见SBMU MCAN调试协议）";
CM_ SG_ 2416045647 S2P_DIAG_BYTE6_15 "SBMU发送到PC的诊断报文（详见SBMU MCAN调试协议）";
CM_ SG_ 2416045647 S2P_DIAG_BYTE7_15 "SBMU发送到PC的诊断报文（详见SBMU MCAN调试协议）";
CM_ SG_ 2416045647 S2P_DIAG_BYTE8_15 "SBMU发送到PC的诊断报文（详见SBMU MCAN调试协议）";
CM_ SG_ 2416045648 S2P_DIAG_BYTE1_16 "SBMU发送到PC的诊断报文（详见SBMU MCAN调试协议）";
CM_ SG_ 2416045648 S2P_DIAG_BYTE2_16 "SBMU发送到PC的诊断报文（详见SBMU MCAN调试协议）";
CM_ SG_ 2416045648 S2P_DIAG_BYTE3_16 "SBMU发送到PC的诊断报文（详见SBMU MCAN调试协议）";
CM_ SG_ 2416045648 S2P_DIAG_BYTE4_16 "SBMU发送到PC的诊断报文（详见SBMU MCAN调试协议）";
CM_ SG_ 2416045648 S2P_DIAG_BYTE5_16 "SBMU发送到PC的诊断报文（详见SBMU MCAN调试协议）";
CM_ SG_ 2416045648 S2P_DIAG_BYTE6_16 "SBMU发送到PC的诊断报文（详见SBMU MCAN调试协议）";
CM_ SG_ 2416045648 S2P_DIAG_BYTE7_16 "SBMU发送到PC的诊断报文（详见SBMU MCAN调试协议）";
CM_ SG_ 2416045648 S2P_DIAG_BYTE8_16 "SBMU发送到PC的诊断报文（详见SBMU MCAN调试协议）";
CM_ SG_ 2416045649 S2P_DIAG_BYTE1_17 "SBMU发送到PC的诊断报文（详见SBMU MCAN调试协议）";
CM_ SG_ 2416045649 S2P_DIAG_BYTE2_17 "SBMU发送到PC的诊断报文（详见SBMU MCAN调试协议）";
CM_ SG_ 2416045649 S2P_DIAG_BYTE3_17 "SBMU发送到PC的诊断报文（详见SBMU MCAN调试协议）";
CM_ SG_ 2416045649 S2P_DIAG_BYTE4_17 "SBMU发送到PC的诊断报文（详见SBMU MCAN调试协议）";
CM_ SG_ 2416045649 S2P_DIAG_BYTE5_17 "SBMU发送到PC的诊断报文（详见SBMU MCAN调试协议）";
CM_ SG_ 2416045649 S2P_DIAG_BYTE6_17 "SBMU发送到PC的诊断报文（详见SBMU MCAN调试协议）";
CM_ SG_ 2416045649 S2P_DIAG_BYTE7_17 "SBMU发送到PC的诊断报文（详见SBMU MCAN调试协议）";
CM_ SG_ 2416045649 S2P_DIAG_BYTE8_17 "SBMU发送到PC的诊断报文（详见SBMU MCAN调试协议）";
CM_ SG_ 2416045650 S2P_DIAG_BYTE1_18 "SBMU发送到PC的诊断报文（详见SBMU MCAN调试协议）";
CM_ SG_ 2416045650 S2P_DIAG_BYTE2_18 "SBMU发送到PC的诊断报文（详见SBMU MCAN调试协议）";
CM_ SG_ 2416045650 S2P_DIAG_BYTE3_18 "SBMU发送到PC的诊断报文（详见SBMU MCAN调试协议）";
CM_ SG_ 2416045650 S2P_DIAG_BYTE4_18 "SBMU发送到PC的诊断报文（详见SBMU MCAN调试协议）";
CM_ SG_ 2416045650 S2P_DIAG_BYTE5_18 "SBMU发送到PC的诊断报文（详见SBMU MCAN调试协议）";
CM_ SG_ 2416045650 S2P_DIAG_BYTE6_18 "SBMU发送到PC的诊断报文（详见SBMU MCAN调试协议）";
CM_ SG_ 2416045650 S2P_DIAG_BYTE7_18 "SBMU发送到PC的诊断报文（详见SBMU MCAN调试协议）";
CM_ SG_ 2416045650 S2P_DIAG_BYTE8_18 "SBMU发送到PC的诊断报文（详见SBMU MCAN调试协议）";
CM_ SG_ 2416045651 S2P_DIAG_BYTE1_19 "SBMU发送到PC的诊断报文（详见SBMU MCAN调试协议）";
CM_ SG_ 2416045651 S2P_DIAG_BYTE2_19 "SBMU发送到PC的诊断报文（详见SBMU MCAN调试协议）";
CM_ SG_ 2416045651 S2P_DIAG_BYTE3_19 "SBMU发送到PC的诊断报文（详见SBMU MCAN调试协议）";
CM_ SG_ 2416045651 S2P_DIAG_BYTE4_19 "SBMU发送到PC的诊断报文（详见SBMU MCAN调试协议）";
CM_ SG_ 2416045651 S2P_DIAG_BYTE5_19 "SBMU发送到PC的诊断报文（详见SBMU MCAN调试协议）";
CM_ SG_ 2416045651 S2P_DIAG_BYTE6_19 "SBMU发送到PC的诊断报文（详见SBMU MCAN调试协议）";
CM_ SG_ 2416045651 S2P_DIAG_BYTE7_19 "SBMU发送到PC的诊断报文（详见SBMU MCAN调试协议）";
CM_ SG_ 2416045651 S2P_DIAG_BYTE8_19 "SBMU发送到PC的诊断报文（详见SBMU MCAN调试协议）";
CM_ SG_ 2416045652 S2P_DIAG_BYTE1_20 "SBMU发送到PC的诊断报文（详见SBMU MCAN调试协议）";
CM_ SG_ 2416045652 S2P_DIAG_BYTE2_20 "SBMU发送到PC的诊断报文（详见SBMU MCAN调试协议）";
CM_ SG_ 2416045652 S2P_DIAG_BYTE3_20 "SBMU发送到PC的诊断报文（详见SBMU MCAN调试协议）";
CM_ SG_ 2416045652 S2P_DIAG_BYTE4_20 "SBMU发送到PC的诊断报文（详见SBMU MCAN调试协议）";
CM_ SG_ 2416045652 S2P_DIAG_BYTE5_20 "SBMU发送到PC的诊断报文（详见SBMU MCAN调试协议）";
CM_ SG_ 2416045652 S2P_DIAG_BYTE6_20 "SBMU发送到PC的诊断报文（详见SBMU MCAN调试协议）";
CM_ SG_ 2416045652 S2P_DIAG_BYTE7_20 "SBMU发送到PC的诊断报文（详见SBMU MCAN调试协议）";
CM_ SG_ 2416045652 S2P_DIAG_BYTE8_20 "SBMU发送到PC的诊断报文（详见SBMU MCAN调试协议）";
CM_ SG_ 2416045653 S2P_DIAG_BYTE1_21 "SBMU发送到PC的诊断报文（详见SBMU MCAN调试协议）";
CM_ SG_ 2416045653 S2P_DIAG_BYTE2_21 "SBMU发送到PC的诊断报文（详见SBMU MCAN调试协议）";
CM_ SG_ 2416045653 S2P_DIAG_BYTE3_21 "SBMU发送到PC的诊断报文（详见SBMU MCAN调试协议）";
CM_ SG_ 2416045653 S2P_DIAG_BYTE4_21 "SBMU发送到PC的诊断报文（详见SBMU MCAN调试协议）";
CM_ SG_ 2416045653 S2P_DIAG_BYTE5_21 "SBMU发送到PC的诊断报文（详见SBMU MCAN调试协议）";
CM_ SG_ 2416045653 S2P_DIAG_BYTE6_21 "SBMU发送到PC的诊断报文（详见SBMU MCAN调试协议）";
CM_ SG_ 2416045653 S2P_DIAG_BYTE7_21 "SBMU发送到PC的诊断报文（详见SBMU MCAN调试协议）";
CM_ SG_ 2416045653 S2P_DIAG_BYTE8_21 "SBMU发送到PC的诊断报文（详见SBMU MCAN调试协议）";
CM_ SG_ 2416045654 S2P_DIAG_BYTE1_22 "SBMU发送到PC的诊断报文（详见SBMU MCAN调试协议）";
CM_ SG_ 2416045654 S2P_DIAG_BYTE2_22 "SBMU发送到PC的诊断报文（详见SBMU MCAN调试协议）";
CM_ SG_ 2416045654 S2P_DIAG_BYTE3_22 "SBMU发送到PC的诊断报文（详见SBMU MCAN调试协议）";
CM_ SG_ 2416045654 S2P_DIAG_BYTE4_22 "SBMU发送到PC的诊断报文（详见SBMU MCAN调试协议）";
CM_ SG_ 2416045654 S2P_DIAG_BYTE5_22 "SBMU发送到PC的诊断报文（详见SBMU MCAN调试协议）";
CM_ SG_ 2416045654 S2P_DIAG_BYTE6_22 "SBMU发送到PC的诊断报文（详见SBMU MCAN调试协议）";
CM_ SG_ 2416045654 S2P_DIAG_BYTE7_22 "SBMU发送到PC的诊断报文（详见SBMU MCAN调试协议）";
CM_ SG_ 2416045654 S2P_DIAG_BYTE8_22 "SBMU发送到PC的诊断报文（详见SBMU MCAN调试协议）";
CM_ SG_ 2416045655 S2P_DIAG_BYTE1_23 "SBMU发送到PC的诊断报文（详见SBMU MCAN调试协议）";
CM_ SG_ 2416045655 S2P_DIAG_BYTE2_23 "SBMU发送到PC的诊断报文（详见SBMU MCAN调试协议）";
CM_ SG_ 2416045655 S2P_DIAG_BYTE3_23 "SBMU发送到PC的诊断报文（详见SBMU MCAN调试协议）";
CM_ SG_ 2416045655 S2P_DIAG_BYTE4_23 "SBMU发送到PC的诊断报文（详见SBMU MCAN调试协议）";
CM_ SG_ 2416045655 S2P_DIAG_BYTE5_23 "SBMU发送到PC的诊断报文（详见SBMU MCAN调试协议）";
CM_ SG_ 2416045655 S2P_DIAG_BYTE6_23 "SBMU发送到PC的诊断报文（详见SBMU MCAN调试协议）";
CM_ SG_ 2416045655 S2P_DIAG_BYTE7_23 "SBMU发送到PC的诊断报文（详见SBMU MCAN调试协议）";
CM_ SG_ 2416045655 S2P_DIAG_BYTE8_23 "SBMU发送到PC的诊断报文（详见SBMU MCAN调试协议）";
CM_ SG_ 2416045656 S2P_DIAG_BYTE1_24 "SBMU发送到PC的诊断报文（详见SBMU MCAN调试协议）";
CM_ SG_ 2416045656 S2P_DIAG_BYTE2_24 "SBMU发送到PC的诊断报文（详见SBMU MCAN调试协议）";
CM_ SG_ 2416045656 S2P_DIAG_BYTE3_24 "SBMU发送到PC的诊断报文（详见SBMU MCAN调试协议）";
CM_ SG_ 2416045656 S2P_DIAG_BYTE4_24 "SBMU发送到PC的诊断报文（详见SBMU MCAN调试协议）";
CM_ SG_ 2416045656 S2P_DIAG_BYTE5_24 "SBMU发送到PC的诊断报文（详见SBMU MCAN调试协议）";
CM_ SG_ 2416045656 S2P_DIAG_BYTE6_24 "SBMU发送到PC的诊断报文（详见SBMU MCAN调试协议）";
CM_ SG_ 2416045656 S2P_DIAG_BYTE7_24 "SBMU发送到PC的诊断报文（详见SBMU MCAN调试协议）";
CM_ SG_ 2416045656 S2P_DIAG_BYTE8_24 "SBMU发送到PC的诊断报文（详见SBMU MCAN调试协议）";
CM_ SG_ 2416045657 S2P_DIAG_BYTE1_25 "SBMU发送到PC的诊断报文（详见SBMU MCAN调试协议）";
CM_ SG_ 2416045657 S2P_DIAG_BYTE2_25 "SBMU发送到PC的诊断报文（详见SBMU MCAN调试协议）";
CM_ SG_ 2416045657 S2P_DIAG_BYTE3_25 "SBMU发送到PC的诊断报文（详见SBMU MCAN调试协议）";
CM_ SG_ 2416045657 S2P_DIAG_BYTE4_25 "SBMU发送到PC的诊断报文（详见SBMU MCAN调试协议）";
CM_ SG_ 2416045657 S2P_DIAG_BYTE5_25 "SBMU发送到PC的诊断报文（详见SBMU MCAN调试协议）";
CM_ SG_ 2416045657 S2P_DIAG_BYTE6_25 "SBMU发送到PC的诊断报文（详见SBMU MCAN调试协议）";
CM_ SG_ 2416045657 S2P_DIAG_BYTE7_25 "SBMU发送到PC的诊断报文（详见SBMU MCAN调试协议）";
CM_ SG_ 2416045657 S2P_DIAG_BYTE8_25 "SBMU发送到PC的诊断报文（详见SBMU MCAN调试协议）";
CM_ SG_ 2416045658 S2P_DIAG_BYTE1_26 "SBMU发送到PC的诊断报文（详见SBMU MCAN调试协议）";
CM_ SG_ 2416045658 S2P_DIAG_BYTE2_26 "SBMU发送到PC的诊断报文（详见SBMU MCAN调试协议）";
CM_ SG_ 2416045658 S2P_DIAG_BYTE3_26 "SBMU发送到PC的诊断报文（详见SBMU MCAN调试协议）";
CM_ SG_ 2416045658 S2P_DIAG_BYTE4_26 "SBMU发送到PC的诊断报文（详见SBMU MCAN调试协议）";
CM_ SG_ 2416045658 S2P_DIAG_BYTE5_26 "SBMU发送到PC的诊断报文（详见SBMU MCAN调试协议）";
CM_ SG_ 2416045658 S2P_DIAG_BYTE6_26 "SBMU发送到PC的诊断报文（详见SBMU MCAN调试协议）";
CM_ SG_ 2416045658 S2P_DIAG_BYTE7_26 "SBMU发送到PC的诊断报文（详见SBMU MCAN调试协议）";
CM_ SG_ 2416045658 S2P_DIAG_BYTE8_26 "SBMU发送到PC的诊断报文（详见SBMU MCAN调试协议）";
CM_ SG_ 2416045659 S2P_DIAG_BYTE1_27 "SBMU发送到PC的诊断报文（详见SBMU MCAN调试协议）";
CM_ SG_ 2416045659 S2P_DIAG_BYTE2_27 "SBMU发送到PC的诊断报文（详见SBMU MCAN调试协议）";
CM_ SG_ 2416045659 S2P_DIAG_BYTE3_27 "SBMU发送到PC的诊断报文（详见SBMU MCAN调试协议）";
CM_ SG_ 2416045659 S2P_DIAG_BYTE4_27 "SBMU发送到PC的诊断报文（详见SBMU MCAN调试协议）";
CM_ SG_ 2416045659 S2P_DIAG_BYTE5_27 "SBMU发送到PC的诊断报文（详见SBMU MCAN调试协议）";
CM_ SG_ 2416045659 S2P_DIAG_BYTE6_27 "SBMU发送到PC的诊断报文（详见SBMU MCAN调试协议）";
CM_ SG_ 2416045659 S2P_DIAG_BYTE7_27 "SBMU发送到PC的诊断报文（详见SBMU MCAN调试协议）";
CM_ SG_ 2416045659 S2P_DIAG_BYTE8_27 "SBMU发送到PC的诊断报文（详见SBMU MCAN调试协议）";
CM_ SG_ 2416045660 S2P_DIAG_BYTE1_28 "SBMU发送到PC的诊断报文（详见SBMU MCAN调试协议）";
CM_ SG_ 2416045660 S2P_DIAG_BYTE2_28 "SBMU发送到PC的诊断报文（详见SBMU MCAN调试协议）";
CM_ SG_ 2416045660 S2P_DIAG_BYTE3_28 "SBMU发送到PC的诊断报文（详见SBMU MCAN调试协议）";
CM_ SG_ 2416045660 S2P_DIAG_BYTE4_28 "SBMU发送到PC的诊断报文（详见SBMU MCAN调试协议）";
CM_ SG_ 2416045660 S2P_DIAG_BYTE5_28 "SBMU发送到PC的诊断报文（详见SBMU MCAN调试协议）";
CM_ SG_ 2416045660 S2P_DIAG_BYTE6_28 "SBMU发送到PC的诊断报文（详见SBMU MCAN调试协议）";
CM_ SG_ 2416045660 S2P_DIAG_BYTE7_28 "SBMU发送到PC的诊断报文（详见SBMU MCAN调试协议）";
CM_ SG_ 2416045660 S2P_DIAG_BYTE8_28 "SBMU发送到PC的诊断报文（详见SBMU MCAN调试协议）";
CM_ SG_ 2416045661 S2P_DIAG_BYTE1_29 "SBMU发送到PC的诊断报文（详见SBMU MCAN调试协议）";
CM_ SG_ 2416045661 S2P_DIAG_BYTE2_29 "SBMU发送到PC的诊断报文（详见SBMU MCAN调试协议）";
CM_ SG_ 2416045661 S2P_DIAG_BYTE3_29 "SBMU发送到PC的诊断报文（详见SBMU MCAN调试协议）";
CM_ SG_ 2416045661 S2P_DIAG_BYTE4_29 "SBMU发送到PC的诊断报文（详见SBMU MCAN调试协议）";
CM_ SG_ 2416045661 S2P_DIAG_BYTE5_29 "SBMU发送到PC的诊断报文（详见SBMU MCAN调试协议）";
CM_ SG_ 2416045661 S2P_DIAG_BYTE6_29 "SBMU发送到PC的诊断报文（详见SBMU MCAN调试协议）";
CM_ SG_ 2416045661 S2P_DIAG_BYTE7_29 "SBMU发送到PC的诊断报文（详见SBMU MCAN调试协议）";
CM_ SG_ 2416045661 S2P_DIAG_BYTE8_29 "SBMU发送到PC的诊断报文（详见SBMU MCAN调试协议）";
CM_ SG_ 2416045662 S2P_DIAG_BYTE1_30 "SBMU发送到PC的诊断报文（详见SBMU MCAN调试协议）";
CM_ SG_ 2416045662 S2P_DIAG_BYTE2_30 "SBMU发送到PC的诊断报文（详见SBMU MCAN调试协议）";
CM_ SG_ 2416045662 S2P_DIAG_BYTE3_30 "SBMU发送到PC的诊断报文（详见SBMU MCAN调试协议）";
CM_ SG_ 2416045662 S2P_DIAG_BYTE4_30 "SBMU发送到PC的诊断报文（详见SBMU MCAN调试协议）";
CM_ SG_ 2416045662 S2P_DIAG_BYTE5_30 "SBMU发送到PC的诊断报文（详见SBMU MCAN调试协议）";
CM_ SG_ 2416045662 S2P_DIAG_BYTE6_30 "SBMU发送到PC的诊断报文（详见SBMU MCAN调试协议）";
CM_ SG_ 2416045662 S2P_DIAG_BYTE7_30 "SBMU发送到PC的诊断报文（详见SBMU MCAN调试协议）";
CM_ SG_ 2416045662 S2P_DIAG_BYTE8_30 "SBMU发送到PC的诊断报文（详见SBMU MCAN调试协议）";
CM_ SG_ 2416045663 S2P_DIAG_BYTE1_31 "SBMU发送到PC的诊断报文（详见SBMU MCAN调试协议）";
CM_ SG_ 2416045663 S2P_DIAG_BYTE2_31 "SBMU发送到PC的诊断报文（详见SBMU MCAN调试协议）";
CM_ SG_ 2416045663 S2P_DIAG_BYTE3_31 "SBMU发送到PC的诊断报文（详见SBMU MCAN调试协议）";
CM_ SG_ 2416045663 S2P_DIAG_BYTE4_31 "SBMU发送到PC的诊断报文（详见SBMU MCAN调试协议）";
CM_ SG_ 2416045663 S2P_DIAG_BYTE5_31 "SBMU发送到PC的诊断报文（详见SBMU MCAN调试协议）";
CM_ SG_ 2416045663 S2P_DIAG_BYTE6_31 "SBMU发送到PC的诊断报文（详见SBMU MCAN调试协议）";
CM_ SG_ 2416045663 S2P_DIAG_BYTE7_31 "SBMU发送到PC的诊断报文（详见SBMU MCAN调试协议）";
CM_ SG_ 2416045663 S2P_DIAG_BYTE8_31 "SBMU发送到PC的诊断报文（详见SBMU MCAN调试协议）";
CM_ SG_ 2416045664 S2P_DIAG_BYTE1_32 "SBMU发送到PC的诊断报文（详见SBMU MCAN调试协议）";
CM_ SG_ 2416045664 S2P_DIAG_BYTE2_32 "SBMU发送到PC的诊断报文（详见SBMU MCAN调试协议）";
CM_ SG_ 2416045664 S2P_DIAG_BYTE3_32 "SBMU发送到PC的诊断报文（详见SBMU MCAN调试协议）";
CM_ SG_ 2416045664 S2P_DIAG_BYTE4_32 "SBMU发送到PC的诊断报文（详见SBMU MCAN调试协议）";
CM_ SG_ 2416045664 S2P_DIAG_BYTE5_32 "SBMU发送到PC的诊断报文（详见SBMU MCAN调试协议）";
CM_ SG_ 2416045664 S2P_DIAG_BYTE6_32 "SBMU发送到PC的诊断报文（详见SBMU MCAN调试协议）";
CM_ SG_ 2416045664 S2P_DIAG_BYTE7_32 "SBMU发送到PC的诊断报文（详见SBMU MCAN调试协议）";
CM_ SG_ 2416045664 S2P_DIAG_BYTE8_32 "SBMU发送到PC的诊断报文（详见SBMU MCAN调试协议）";
CM_ SG_ 2416045665 S2P_DIAG_BYTE1_33 "SBMU发送到PC的诊断报文（详见SBMU MCAN调试协议）";
CM_ SG_ 2416045665 S2P_DIAG_BYTE2_33 "SBMU发送到PC的诊断报文（详见SBMU MCAN调试协议）";
CM_ SG_ 2416045665 S2P_DIAG_BYTE3_33 "SBMU发送到PC的诊断报文（详见SBMU MCAN调试协议）";
CM_ SG_ 2416045665 S2P_DIAG_BYTE4_33 "SBMU发送到PC的诊断报文（详见SBMU MCAN调试协议）";
CM_ SG_ 2416045665 S2P_DIAG_BYTE5_33 "SBMU发送到PC的诊断报文（详见SBMU MCAN调试协议）";
CM_ SG_ 2416045665 S2P_DIAG_BYTE6_33 "SBMU发送到PC的诊断报文（详见SBMU MCAN调试协议）";
CM_ SG_ 2416045665 S2P_DIAG_BYTE7_33 "SBMU发送到PC的诊断报文（详见SBMU MCAN调试协议）";
CM_ SG_ 2416045665 S2P_DIAG_BYTE8_33 "SBMU发送到PC的诊断报文（详见SBMU MCAN调试协议）";
CM_ SG_ 2416045666 S2P_DIAG_BYTE1_34 "SBMU发送到PC的诊断报文（详见SBMU MCAN调试协议）";
CM_ SG_ 2416045666 S2P_DIAG_BYTE2_34 "SBMU发送到PC的诊断报文（详见SBMU MCAN调试协议）";
CM_ SG_ 2416045666 S2P_DIAG_BYTE3_34 "SBMU发送到PC的诊断报文（详见SBMU MCAN调试协议）";
CM_ SG_ 2416045666 S2P_DIAG_BYTE4_34 "SBMU发送到PC的诊断报文（详见SBMU MCAN调试协议）";
CM_ SG_ 2416045666 S2P_DIAG_BYTE5_34 "SBMU发送到PC的诊断报文（详见SBMU MCAN调试协议）";
CM_ SG_ 2416045666 S2P_DIAG_BYTE6_34 "SBMU发送到PC的诊断报文（详见SBMU MCAN调试协议）";
CM_ SG_ 2416045666 S2P_DIAG_BYTE7_34 "SBMU发送到PC的诊断报文（详见SBMU MCAN调试协议）";
CM_ SG_ 2416045666 S2P_DIAG_BYTE8_34 "SBMU发送到PC的诊断报文（详见SBMU MCAN调试协议）";
CM_ SG_ 2416045667 S2P_DIAG_BYTE1_35 "SBMU发送到PC的诊断报文（详见SBMU MCAN调试协议）";
CM_ SG_ 2416045667 S2P_DIAG_BYTE2_35 "SBMU发送到PC的诊断报文（详见SBMU MCAN调试协议）";
CM_ SG_ 2416045667 S2P_DIAG_BYTE3_35 "SBMU发送到PC的诊断报文（详见SBMU MCAN调试协议）";
CM_ SG_ 2416045667 S2P_DIAG_BYTE4_35 "SBMU发送到PC的诊断报文（详见SBMU MCAN调试协议）";
CM_ SG_ 2416045667 S2P_DIAG_BYTE5_35 "SBMU发送到PC的诊断报文（详见SBMU MCAN调试协议）";
CM_ SG_ 2416045667 S2P_DIAG_BYTE6_35 "SBMU发送到PC的诊断报文（详见SBMU MCAN调试协议）";
CM_ SG_ 2416045667 S2P_DIAG_BYTE7_35 "SBMU发送到PC的诊断报文（详见SBMU MCAN调试协议）";
CM_ SG_ 2416045667 S2P_DIAG_BYTE8_35 "SBMU发送到PC的诊断报文（详见SBMU MCAN调试协议）";
CM_ SG_ 2416045668 S2P_DIAG_BYTE1_36 "SBMU发送到PC的诊断报文（详见SBMU MCAN调试协议）";
CM_ SG_ 2416045668 S2P_DIAG_BYTE2_36 "SBMU发送到PC的诊断报文（详见SBMU MCAN调试协议）";
CM_ SG_ 2416045668 S2P_DIAG_BYTE3_36 "SBMU发送到PC的诊断报文（详见SBMU MCAN调试协议）";
CM_ SG_ 2416045668 S2P_DIAG_BYTE4_36 "SBMU发送到PC的诊断报文（详见SBMU MCAN调试协议）";
CM_ SG_ 2416045668 S2P_DIAG_BYTE5_36 "SBMU发送到PC的诊断报文（详见SBMU MCAN调试协议）";
CM_ SG_ 2416045668 S2P_DIAG_BYTE6_36 "SBMU发送到PC的诊断报文（详见SBMU MCAN调试协议）";
CM_ SG_ 2416045668 S2P_DIAG_BYTE7_36 "SBMU发送到PC的诊断报文（详见SBMU MCAN调试协议）";
CM_ SG_ 2416045668 S2P_DIAG_BYTE8_36 "SBMU发送到PC的诊断报文（详见SBMU MCAN调试协议）";
CM_ SG_ 2416045669 S2P_DIAG_BYTE1_37 "SBMU发送到PC的诊断报文（详见SBMU MCAN调试协议）";
CM_ SG_ 2416045669 S2P_DIAG_BYTE2_37 "SBMU发送到PC的诊断报文（详见SBMU MCAN调试协议）";
CM_ SG_ 2416045669 S2P_DIAG_BYTE3_37 "SBMU发送到PC的诊断报文（详见SBMU MCAN调试协议）";
CM_ SG_ 2416045669 S2P_DIAG_BYTE4_37 "SBMU发送到PC的诊断报文（详见SBMU MCAN调试协议）";
CM_ SG_ 2416045669 S2P_DIAG_BYTE5_37 "SBMU发送到PC的诊断报文（详见SBMU MCAN调试协议）";
CM_ SG_ 2416045669 S2P_DIAG_BYTE6_37 "SBMU发送到PC的诊断报文（详见SBMU MCAN调试协议）";
CM_ SG_ 2416045669 S2P_DIAG_BYTE7_37 "SBMU发送到PC的诊断报文（详见SBMU MCAN调试协议）";
CM_ SG_ 2416045669 S2P_DIAG_BYTE8_37 "SBMU发送到PC的诊断报文（详见SBMU MCAN调试协议）";
CM_ SG_ 2416045670 S2P_DIAG_BYTE1_38 "SBMU发送到PC的诊断报文（详见SBMU MCAN调试协议）";
CM_ SG_ 2416045670 S2P_DIAG_BYTE2_38 "SBMU发送到PC的诊断报文（详见SBMU MCAN调试协议）";
CM_ SG_ 2416045670 S2P_DIAG_BYTE3_38 "SBMU发送到PC的诊断报文（详见SBMU MCAN调试协议）";
CM_ SG_ 2416045670 S2P_DIAG_BYTE4_38 "SBMU发送到PC的诊断报文（详见SBMU MCAN调试协议）";
CM_ SG_ 2416045670 S2P_DIAG_BYTE5_38 "SBMU发送到PC的诊断报文（详见SBMU MCAN调试协议）";
CM_ SG_ 2416045670 S2P_DIAG_BYTE6_38 "SBMU发送到PC的诊断报文（详见SBMU MCAN调试协议）";
CM_ SG_ 2416045670 S2P_DIAG_BYTE7_38 "SBMU发送到PC的诊断报文（详见SBMU MCAN调试协议）";
CM_ SG_ 2416045670 S2P_DIAG_BYTE8_38 "SBMU发送到PC的诊断报文（详见SBMU MCAN调试协议）";
CM_ SG_ 2416045671 S2P_DIAG_BYTE1_39 "SBMU发送到PC的诊断报文（详见SBMU MCAN调试协议）";
CM_ SG_ 2416045671 S2P_DIAG_BYTE2_39 "SBMU发送到PC的诊断报文（详见SBMU MCAN调试协议）";
CM_ SG_ 2416045671 S2P_DIAG_BYTE3_39 "SBMU发送到PC的诊断报文（详见SBMU MCAN调试协议）";
CM_ SG_ 2416045671 S2P_DIAG_BYTE4_39 "SBMU发送到PC的诊断报文（详见SBMU MCAN调试协议）";
CM_ SG_ 2416045671 S2P_DIAG_BYTE5_39 "SBMU发送到PC的诊断报文（详见SBMU MCAN调试协议）";
CM_ SG_ 2416045671 S2P_DIAG_BYTE6_39 "SBMU发送到PC的诊断报文（详见SBMU MCAN调试协议）";
CM_ SG_ 2416045671 S2P_DIAG_BYTE7_39 "SBMU发送到PC的诊断报文（详见SBMU MCAN调试协议）";
CM_ SG_ 2416045671 S2P_DIAG_BYTE8_39 "SBMU发送到PC的诊断报文（详见SBMU MCAN调试协议）";
CM_ SG_ 2416045672 S2P_DIAG_BYTE1_40 "SBMU发送到PC的诊断报文（详见SBMU MCAN调试协议）";
CM_ SG_ 2416045672 S2P_DIAG_BYTE2_40 "SBMU发送到PC的诊断报文（详见SBMU MCAN调试协议）";
CM_ SG_ 2416045672 S2P_DIAG_BYTE3_40 "SBMU发送到PC的诊断报文（详见SBMU MCAN调试协议）";
CM_ SG_ 2416045672 S2P_DIAG_BYTE4_40 "SBMU发送到PC的诊断报文（详见SBMU MCAN调试协议）";
CM_ SG_ 2416045672 S2P_DIAG_BYTE5_40 "SBMU发送到PC的诊断报文（详见SBMU MCAN调试协议）";
CM_ SG_ 2416045672 S2P_DIAG_BYTE6_40 "SBMU发送到PC的诊断报文（详见SBMU MCAN调试协议）";
CM_ SG_ 2416045672 S2P_DIAG_BYTE7_40 "SBMU发送到PC的诊断报文（详见SBMU MCAN调试协议）";
CM_ SG_ 2416045672 S2P_DIAG_BYTE8_40 "SBMU发送到PC的诊断报文（详见SBMU MCAN调试协议）";
CM_ SG_ 2416045673 S2P_DIAG_BYTE1_41 "SBMU发送到PC的诊断报文（详见SBMU MCAN调试协议）";
CM_ SG_ 2416045673 S2P_DIAG_BYTE2_41 "SBMU发送到PC的诊断报文（详见SBMU MCAN调试协议）";
CM_ SG_ 2416045673 S2P_DIAG_BYTE3_41 "SBMU发送到PC的诊断报文（详见SBMU MCAN调试协议）";
CM_ SG_ 2416045673 S2P_DIAG_BYTE4_41 "SBMU发送到PC的诊断报文（详见SBMU MCAN调试协议）";
CM_ SG_ 2416045673 S2P_DIAG_BYTE5_41 "SBMU发送到PC的诊断报文（详见SBMU MCAN调试协议）";
CM_ SG_ 2416045673 S2P_DIAG_BYTE6_41 "SBMU发送到PC的诊断报文（详见SBMU MCAN调试协议）";
CM_ SG_ 2416045673 S2P_DIAG_BYTE7_41 "SBMU发送到PC的诊断报文（详见SBMU MCAN调试协议）";
CM_ SG_ 2416045673 S2P_DIAG_BYTE8_41 "SBMU发送到PC的诊断报文（详见SBMU MCAN调试协议）";
CM_ SG_ 2416045674 S2P_DIAG_BYTE1_42 "SBMU发送到PC的诊断报文（详见SBMU MCAN调试协议）";
CM_ SG_ 2416045674 S2P_DIAG_BYTE2_42 "SBMU发送到PC的诊断报文（详见SBMU MCAN调试协议）";
CM_ SG_ 2416045674 S2P_DIAG_BYTE3_42 "SBMU发送到PC的诊断报文（详见SBMU MCAN调试协议）";
CM_ SG_ 2416045674 S2P_DIAG_BYTE4_42 "SBMU发送到PC的诊断报文（详见SBMU MCAN调试协议）";
CM_ SG_ 2416045674 S2P_DIAG_BYTE5_42 "SBMU发送到PC的诊断报文（详见SBMU MCAN调试协议）";
CM_ SG_ 2416045674 S2P_DIAG_BYTE6_42 "SBMU发送到PC的诊断报文（详见SBMU MCAN调试协议）";
CM_ SG_ 2416045674 S2P_DIAG_BYTE7_42 "SBMU发送到PC的诊断报文（详见SBMU MCAN调试协议）";
CM_ SG_ 2416045674 S2P_DIAG_BYTE8_42 "SBMU发送到PC的诊断报文（详见SBMU MCAN调试协议）";
CM_ SG_ 2416045675 S2P_DIAG_BYTE1_43 "SBMU发送到PC的诊断报文（详见SBMU MCAN调试协议）";
CM_ SG_ 2416045675 S2P_DIAG_BYTE2_43 "SBMU发送到PC的诊断报文（详见SBMU MCAN调试协议）";
CM_ SG_ 2416045675 S2P_DIAG_BYTE3_43 "SBMU发送到PC的诊断报文（详见SBMU MCAN调试协议）";
CM_ SG_ 2416045675 S2P_DIAG_BYTE4_43 "SBMU发送到PC的诊断报文（详见SBMU MCAN调试协议）";
CM_ SG_ 2416045675 S2P_DIAG_BYTE5_43 "SBMU发送到PC的诊断报文（详见SBMU MCAN调试协议）";
CM_ SG_ 2416045675 S2P_DIAG_BYTE6_43 "SBMU发送到PC的诊断报文（详见SBMU MCAN调试协议）";
CM_ SG_ 2416045675 S2P_DIAG_BYTE7_43 "SBMU发送到PC的诊断报文（详见SBMU MCAN调试协议）";
CM_ SG_ 2416045675 S2P_DIAG_BYTE8_43 "SBMU发送到PC的诊断报文（详见SBMU MCAN调试协议）";
CM_ SG_ 2416045676 S2P_DIAG_BYTE1_44 "SBMU发送到PC的诊断报文（详见SBMU MCAN调试协议）";
CM_ SG_ 2416045676 S2P_DIAG_BYTE2_44 "SBMU发送到PC的诊断报文（详见SBMU MCAN调试协议）";
CM_ SG_ 2416045676 S2P_DIAG_BYTE3_44 "SBMU发送到PC的诊断报文（详见SBMU MCAN调试协议）";
CM_ SG_ 2416045676 S2P_DIAG_BYTE4_44 "SBMU发送到PC的诊断报文（详见SBMU MCAN调试协议）";
CM_ SG_ 2416045676 S2P_DIAG_BYTE5_44 "SBMU发送到PC的诊断报文（详见SBMU MCAN调试协议）";
CM_ SG_ 2416045676 S2P_DIAG_BYTE6_44 "SBMU发送到PC的诊断报文（详见SBMU MCAN调试协议）";
CM_ SG_ 2416045676 S2P_DIAG_BYTE7_44 "SBMU发送到PC的诊断报文（详见SBMU MCAN调试协议）";
CM_ SG_ 2416045676 S2P_DIAG_BYTE8_44 "SBMU发送到PC的诊断报文（详见SBMU MCAN调试协议）";
CM_ SG_ 2416045677 S2P_DIAG_BYTE1_45 "SBMU发送到PC的诊断报文（详见SBMU MCAN调试协议）";
CM_ SG_ 2416045677 S2P_DIAG_BYTE2_45 "SBMU发送到PC的诊断报文（详见SBMU MCAN调试协议）";
CM_ SG_ 2416045677 S2P_DIAG_BYTE3_45 "SBMU发送到PC的诊断报文（详见SBMU MCAN调试协议）";
CM_ SG_ 2416045677 S2P_DIAG_BYTE4_45 "SBMU发送到PC的诊断报文（详见SBMU MCAN调试协议）";
CM_ SG_ 2416045677 S2P_DIAG_BYTE5_45 "SBMU发送到PC的诊断报文（详见SBMU MCAN调试协议）";
CM_ SG_ 2416045677 S2P_DIAG_BYTE6_45 "SBMU发送到PC的诊断报文（详见SBMU MCAN调试协议）";
CM_ SG_ 2416045677 S2P_DIAG_BYTE7_45 "SBMU发送到PC的诊断报文（详见SBMU MCAN调试协议）";
CM_ SG_ 2416045677 S2P_DIAG_BYTE8_45 "SBMU发送到PC的诊断报文（详见SBMU MCAN调试协议）";
CM_ SG_ 2416045678 S2P_DIAG_BYTE1_46 "SBMU发送到PC的诊断报文（详见SBMU MCAN调试协议）";
CM_ SG_ 2416045678 S2P_DIAG_BYTE2_46 "SBMU发送到PC的诊断报文（详见SBMU MCAN调试协议）";
CM_ SG_ 2416045678 S2P_DIAG_BYTE3_46 "SBMU发送到PC的诊断报文（详见SBMU MCAN调试协议）";
CM_ SG_ 2416045678 S2P_DIAG_BYTE4_46 "SBMU发送到PC的诊断报文（详见SBMU MCAN调试协议）";
CM_ SG_ 2416045678 S2P_DIAG_BYTE5_46 "SBMU发送到PC的诊断报文（详见SBMU MCAN调试协议）";
CM_ SG_ 2416045678 S2P_DIAG_BYTE6_46 "SBMU发送到PC的诊断报文（详见SBMU MCAN调试协议）";
CM_ SG_ 2416045678 S2P_DIAG_BYTE7_46 "SBMU发送到PC的诊断报文（详见SBMU MCAN调试协议）";
CM_ SG_ 2416045678 S2P_DIAG_BYTE8_46 "SBMU发送到PC的诊断报文（详见SBMU MCAN调试协议）";
CM_ SG_ 2416045679 S2P_DIAG_BYTE1_47 "SBMU发送到PC的诊断报文（详见SBMU MCAN调试协议）";
CM_ SG_ 2416045679 S2P_DIAG_BYTE2_47 "SBMU发送到PC的诊断报文（详见SBMU MCAN调试协议）";
CM_ SG_ 2416045679 S2P_DIAG_BYTE3_47 "SBMU发送到PC的诊断报文（详见SBMU MCAN调试协议）";
CM_ SG_ 2416045679 S2P_DIAG_BYTE4_47 "SBMU发送到PC的诊断报文（详见SBMU MCAN调试协议）";
CM_ SG_ 2416045679 S2P_DIAG_BYTE5_47 "SBMU发送到PC的诊断报文（详见SBMU MCAN调试协议）";
CM_ SG_ 2416045679 S2P_DIAG_BYTE6_47 "SBMU发送到PC的诊断报文（详见SBMU MCAN调试协议）";
CM_ SG_ 2416045679 S2P_DIAG_BYTE7_47 "SBMU发送到PC的诊断报文（详见SBMU MCAN调试协议）";
CM_ SG_ 2416045679 S2P_DIAG_BYTE8_47 "SBMU发送到PC的诊断报文（详见SBMU MCAN调试协议）";
CM_ SG_ 2416045680 S2P_DIAG_BYTE1_48 "SBMU发送到PC的诊断报文（详见SBMU MCAN调试协议）";
CM_ SG_ 2416045680 S2P_DIAG_BYTE2_48 "SBMU发送到PC的诊断报文（详见SBMU MCAN调试协议）";
CM_ SG_ 2416045680 S2P_DIAG_BYTE3_48 "SBMU发送到PC的诊断报文（详见SBMU MCAN调试协议）";
CM_ SG_ 2416045680 S2P_DIAG_BYTE4_48 "SBMU发送到PC的诊断报文（详见SBMU MCAN调试协议）";
CM_ SG_ 2416045680 S2P_DIAG_BYTE5_48 "SBMU发送到PC的诊断报文（详见SBMU MCAN调试协议）";
CM_ SG_ 2416045680 S2P_DIAG_BYTE6_48 "SBMU发送到PC的诊断报文（详见SBMU MCAN调试协议）";
CM_ SG_ 2416045680 S2P_DIAG_BYTE7_48 "SBMU发送到PC的诊断报文（详见SBMU MCAN调试协议）";
CM_ SG_ 2416045680 S2P_DIAG_BYTE8_48 "SBMU发送到PC的诊断报文（详见SBMU MCAN调试协议）";
CM_ SG_ 2416045681 S2P_DIAG_BYTE1_49 "SBMU发送到PC的诊断报文（详见SBMU MCAN调试协议）";
CM_ SG_ 2416045681 S2P_DIAG_BYTE2_49 "SBMU发送到PC的诊断报文（详见SBMU MCAN调试协议）";
CM_ SG_ 2416045681 S2P_DIAG_BYTE3_49 "SBMU发送到PC的诊断报文（详见SBMU MCAN调试协议）";
CM_ SG_ 2416045681 S2P_DIAG_BYTE4_49 "SBMU发送到PC的诊断报文（详见SBMU MCAN调试协议）";
CM_ SG_ 2416045681 S2P_DIAG_BYTE5_49 "SBMU发送到PC的诊断报文（详见SBMU MCAN调试协议）";
CM_ SG_ 2416045681 S2P_DIAG_BYTE6_49 "SBMU发送到PC的诊断报文（详见SBMU MCAN调试协议）";
CM_ SG_ 2416045681 S2P_DIAG_BYTE7_49 "SBMU发送到PC的诊断报文（详见SBMU MCAN调试协议）";
CM_ SG_ 2416045681 S2P_DIAG_BYTE8_49 "SBMU发送到PC的诊断报文（详见SBMU MCAN调试协议）";
CM_ SG_ 2416045682 S2P_DIAG_BYTE1_50 "SBMU发送到PC的诊断报文（详见SBMU MCAN调试协议）";
CM_ SG_ 2416045682 S2P_DIAG_BYTE2_50 "SBMU发送到PC的诊断报文（详见SBMU MCAN调试协议）";
CM_ SG_ 2416045682 S2P_DIAG_BYTE3_50 "SBMU发送到PC的诊断报文（详见SBMU MCAN调试协议）";
CM_ SG_ 2416045682 S2P_DIAG_BYTE4_50 "SBMU发送到PC的诊断报文（详见SBMU MCAN调试协议）";
CM_ SG_ 2416045682 S2P_DIAG_BYTE5_50 "SBMU发送到PC的诊断报文（详见SBMU MCAN调试协议）";
CM_ SG_ 2416045682 S2P_DIAG_BYTE6_50 "SBMU发送到PC的诊断报文（详见SBMU MCAN调试协议）";
CM_ SG_ 2416045682 S2P_DIAG_BYTE7_50 "SBMU发送到PC的诊断报文（详见SBMU MCAN调试协议）";
CM_ SG_ 2416045682 S2P_DIAG_BYTE8_50 "SBMU发送到PC的诊断报文（详见SBMU MCAN调试协议）";
CM_ SG_ 2416045683 S2P_DIAG_BYTE1_51 "SBMU发送到PC的诊断报文（详见SBMU MCAN调试协议）";
CM_ SG_ 2416045683 S2P_DIAG_BYTE2_51 "SBMU发送到PC的诊断报文（详见SBMU MCAN调试协议）";
CM_ SG_ 2416045683 S2P_DIAG_BYTE3_51 "SBMU发送到PC的诊断报文（详见SBMU MCAN调试协议）";
CM_ SG_ 2416045683 S2P_DIAG_BYTE4_51 "SBMU发送到PC的诊断报文（详见SBMU MCAN调试协议）";
CM_ SG_ 2416045683 S2P_DIAG_BYTE5_51 "SBMU发送到PC的诊断报文（详见SBMU MCAN调试协议）";
CM_ SG_ 2416045683 S2P_DIAG_BYTE6_51 "SBMU发送到PC的诊断报文（详见SBMU MCAN调试协议）";
CM_ SG_ 2416045683 S2P_DIAG_BYTE7_51 "SBMU发送到PC的诊断报文（详见SBMU MCAN调试协议）";
CM_ SG_ 2416045683 S2P_DIAG_BYTE8_51 "SBMU发送到PC的诊断报文（详见SBMU MCAN调试协议）";
CM_ SG_ 2416045684 S2P_DIAG_BYTE1_52 "SBMU发送到PC的诊断报文（详见SBMU MCAN调试协议）";
CM_ SG_ 2416045684 S2P_DIAG_BYTE2_52 "SBMU发送到PC的诊断报文（详见SBMU MCAN调试协议）";
CM_ SG_ 2416045684 S2P_DIAG_BYTE3_52 "SBMU发送到PC的诊断报文（详见SBMU MCAN调试协议）";
CM_ SG_ 2416045684 S2P_DIAG_BYTE4_52 "SBMU发送到PC的诊断报文（详见SBMU MCAN调试协议）";
CM_ SG_ 2416045684 S2P_DIAG_BYTE5_52 "SBMU发送到PC的诊断报文（详见SBMU MCAN调试协议）";
CM_ SG_ 2416045684 S2P_DIAG_BYTE6_52 "SBMU发送到PC的诊断报文（详见SBMU MCAN调试协议）";
CM_ SG_ 2416045684 S2P_DIAG_BYTE7_52 "SBMU发送到PC的诊断报文（详见SBMU MCAN调试协议）";
CM_ SG_ 2416045684 S2P_DIAG_BYTE8_52 "SBMU发送到PC的诊断报文（详见SBMU MCAN调试协议）";
CM_ SG_ 2416045685 S2P_DIAG_BYTE1_53 "SBMU发送到PC的诊断报文（详见SBMU MCAN调试协议）";
CM_ SG_ 2416045685 S2P_DIAG_BYTE2_53 "SBMU发送到PC的诊断报文（详见SBMU MCAN调试协议）";
CM_ SG_ 2416045685 S2P_DIAG_BYTE3_53 "SBMU发送到PC的诊断报文（详见SBMU MCAN调试协议）";
CM_ SG_ 2416045685 S2P_DIAG_BYTE4_53 "SBMU发送到PC的诊断报文（详见SBMU MCAN调试协议）";
CM_ SG_ 2416045685 S2P_DIAG_BYTE5_53 "SBMU发送到PC的诊断报文（详见SBMU MCAN调试协议）";
CM_ SG_ 2416045685 S2P_DIAG_BYTE6_53 "SBMU发送到PC的诊断报文（详见SBMU MCAN调试协议）";
CM_ SG_ 2416045685 S2P_DIAG_BYTE7_53 "SBMU发送到PC的诊断报文（详见SBMU MCAN调试协议）";
CM_ SG_ 2416045685 S2P_DIAG_BYTE8_53 "SBMU发送到PC的诊断报文（详见SBMU MCAN调试协议）";
CM_ SG_ 2416045686 S2P_DIAG_BYTE1_54 "SBMU发送到PC的诊断报文（详见SBMU MCAN调试协议）";
CM_ SG_ 2416045686 S2P_DIAG_BYTE2_54 "SBMU发送到PC的诊断报文（详见SBMU MCAN调试协议）";
CM_ SG_ 2416045686 S2P_DIAG_BYTE3_54 "SBMU发送到PC的诊断报文（详见SBMU MCAN调试协议）";
CM_ SG_ 2416045686 S2P_DIAG_BYTE4_54 "SBMU发送到PC的诊断报文（详见SBMU MCAN调试协议）";
CM_ SG_ 2416045686 S2P_DIAG_BYTE5_54 "SBMU发送到PC的诊断报文（详见SBMU MCAN调试协议）";
CM_ SG_ 2416045686 S2P_DIAG_BYTE6_54 "SBMU发送到PC的诊断报文（详见SBMU MCAN调试协议）";
CM_ SG_ 2416045686 S2P_DIAG_BYTE7_54 "SBMU发送到PC的诊断报文（详见SBMU MCAN调试协议）";
CM_ SG_ 2416045686 S2P_DIAG_BYTE8_54 "SBMU发送到PC的诊断报文（详见SBMU MCAN调试协议）";
CM_ SG_ 2416045687 S2P_DIAG_BYTE1_55 "SBMU发送到PC的诊断报文（详见SBMU MCAN调试协议）";
CM_ SG_ 2416045687 S2P_DIAG_BYTE2_55 "SBMU发送到PC的诊断报文（详见SBMU MCAN调试协议）";
CM_ SG_ 2416045687 S2P_DIAG_BYTE3_55 "SBMU发送到PC的诊断报文（详见SBMU MCAN调试协议）";
CM_ SG_ 2416045687 S2P_DIAG_BYTE4_55 "SBMU发送到PC的诊断报文（详见SBMU MCAN调试协议）";
CM_ SG_ 2416045687 S2P_DIAG_BYTE5_55 "SBMU发送到PC的诊断报文（详见SBMU MCAN调试协议）";
CM_ SG_ 2416045687 S2P_DIAG_BYTE6_55 "SBMU发送到PC的诊断报文（详见SBMU MCAN调试协议）";
CM_ SG_ 2416045687 S2P_DIAG_BYTE7_55 "SBMU发送到PC的诊断报文（详见SBMU MCAN调试协议）";
CM_ SG_ 2416045687 S2P_DIAG_BYTE8_55 "SBMU发送到PC的诊断报文（详见SBMU MCAN调试协议）";
CM_ SG_ 2416045688 S2P_DIAG_BYTE1_56 "SBMU发送到PC的诊断报文（详见SBMU MCAN调试协议）";
CM_ SG_ 2416045688 S2P_DIAG_BYTE2_56 "SBMU发送到PC的诊断报文（详见SBMU MCAN调试协议）";
CM_ SG_ 2416045688 S2P_DIAG_BYTE3_56 "SBMU发送到PC的诊断报文（详见SBMU MCAN调试协议）";
CM_ SG_ 2416045688 S2P_DIAG_BYTE4_56 "SBMU发送到PC的诊断报文（详见SBMU MCAN调试协议）";
CM_ SG_ 2416045688 S2P_DIAG_BYTE5_56 "SBMU发送到PC的诊断报文（详见SBMU MCAN调试协议）";
CM_ SG_ 2416045688 S2P_DIAG_BYTE6_56 "SBMU发送到PC的诊断报文（详见SBMU MCAN调试协议）";
CM_ SG_ 2416045688 S2P_DIAG_BYTE7_56 "SBMU发送到PC的诊断报文（详见SBMU MCAN调试协议）";
CM_ SG_ 2416045688 S2P_DIAG_BYTE8_56 "SBMU发送到PC的诊断报文（详见SBMU MCAN调试协议）";
CM_ SG_ 2416045689 S2P_DIAG_BYTE1_57 "SBMU发送到PC的诊断报文（详见SBMU MCAN调试协议）";
CM_ SG_ 2416045689 S2P_DIAG_BYTE2_57 "SBMU发送到PC的诊断报文（详见SBMU MCAN调试协议）";
CM_ SG_ 2416045689 S2P_DIAG_BYTE3_57 "SBMU发送到PC的诊断报文（详见SBMU MCAN调试协议）";
CM_ SG_ 2416045689 S2P_DIAG_BYTE4_57 "SBMU发送到PC的诊断报文（详见SBMU MCAN调试协议）";
CM_ SG_ 2416045689 S2P_DIAG_BYTE5_57 "SBMU发送到PC的诊断报文（详见SBMU MCAN调试协议）";
CM_ SG_ 2416045689 S2P_DIAG_BYTE6_57 "SBMU发送到PC的诊断报文（详见SBMU MCAN调试协议）";
CM_ SG_ 2416045689 S2P_DIAG_BYTE7_57 "SBMU发送到PC的诊断报文（详见SBMU MCAN调试协议）";
CM_ SG_ 2416045689 S2P_DIAG_BYTE8_57 "SBMU发送到PC的诊断报文（详见SBMU MCAN调试协议）";
CM_ SG_ 2416045690 S2P_DIAG_BYTE1_58 "SBMU发送到PC的诊断报文（详见SBMU MCAN调试协议）";
CM_ SG_ 2416045690 S2P_DIAG_BYTE2_58 "SBMU发送到PC的诊断报文（详见SBMU MCAN调试协议）";
CM_ SG_ 2416045690 S2P_DIAG_BYTE3_58 "SBMU发送到PC的诊断报文（详见SBMU MCAN调试协议）";
CM_ SG_ 2416045690 S2P_DIAG_BYTE4_58 "SBMU发送到PC的诊断报文（详见SBMU MCAN调试协议）";
CM_ SG_ 2416045690 S2P_DIAG_BYTE5_58 "SBMU发送到PC的诊断报文（详见SBMU MCAN调试协议）";
CM_ SG_ 2416045690 S2P_DIAG_BYTE6_58 "SBMU发送到PC的诊断报文（详见SBMU MCAN调试协议）";
CM_ SG_ 2416045690 S2P_DIAG_BYTE7_58 "SBMU发送到PC的诊断报文（详见SBMU MCAN调试协议）";
CM_ SG_ 2416045690 S2P_DIAG_BYTE8_58 "SBMU发送到PC的诊断报文（详见SBMU MCAN调试协议）";
CM_ SG_ 2416045691 S2P_DIAG_BYTE1_59 "SBMU发送到PC的诊断报文（详见SBMU MCAN调试协议）";
CM_ SG_ 2416045691 S2P_DIAG_BYTE2_59 "SBMU发送到PC的诊断报文（详见SBMU MCAN调试协议）";
CM_ SG_ 2416045691 S2P_DIAG_BYTE3_59 "SBMU发送到PC的诊断报文（详见SBMU MCAN调试协议）";
CM_ SG_ 2416045691 S2P_DIAG_BYTE4_59 "SBMU发送到PC的诊断报文（详见SBMU MCAN调试协议）";
CM_ SG_ 2416045691 S2P_DIAG_BYTE5_59 "SBMU发送到PC的诊断报文（详见SBMU MCAN调试协议）";
CM_ SG_ 2416045691 S2P_DIAG_BYTE6_59 "SBMU发送到PC的诊断报文（详见SBMU MCAN调试协议）";
CM_ SG_ 2416045691 S2P_DIAG_BYTE7_59 "SBMU发送到PC的诊断报文（详见SBMU MCAN调试协议）";
CM_ SG_ 2416045691 S2P_DIAG_BYTE8_59 "SBMU发送到PC的诊断报文（详见SBMU MCAN调试协议）";
CM_ SG_ 2416045692 S2P_DIAG_BYTE1_60 "SBMU发送到PC的诊断报文（详见SBMU MCAN调试协议）";
CM_ SG_ 2416045692 S2P_DIAG_BYTE2_60 "SBMU发送到PC的诊断报文（详见SBMU MCAN调试协议）";
CM_ SG_ 2416045692 S2P_DIAG_BYTE3_60 "SBMU发送到PC的诊断报文（详见SBMU MCAN调试协议）";
CM_ SG_ 2416045692 S2P_DIAG_BYTE4_60 "SBMU发送到PC的诊断报文（详见SBMU MCAN调试协议）";
CM_ SG_ 2416045692 S2P_DIAG_BYTE5_60 "SBMU发送到PC的诊断报文（详见SBMU MCAN调试协议）";
CM_ SG_ 2416045692 S2P_DIAG_BYTE6_60 "SBMU发送到PC的诊断报文（详见SBMU MCAN调试协议）";
CM_ SG_ 2416045692 S2P_DIAG_BYTE7_60 "SBMU发送到PC的诊断报文（详见SBMU MCAN调试协议）";
CM_ SG_ 2416045692 S2P_DIAG_BYTE8_60 "SBMU发送到PC的诊断报文（详见SBMU MCAN调试协议）";
CM_ SG_ 2416045693 S2P_DIAG_BYTE1_61 "SBMU发送到PC的诊断报文（详见SBMU MCAN调试协议）";
CM_ SG_ 2416045693 S2P_DIAG_BYTE2_61 "SBMU发送到PC的诊断报文（详见SBMU MCAN调试协议）";
CM_ SG_ 2416045693 S2P_DIAG_BYTE3_61 "SBMU发送到PC的诊断报文（详见SBMU MCAN调试协议）";
CM_ SG_ 2416045693 S2P_DIAG_BYTE4_61 "SBMU发送到PC的诊断报文（详见SBMU MCAN调试协议）";
CM_ SG_ 2416045693 S2P_DIAG_BYTE5_61 "SBMU发送到PC的诊断报文（详见SBMU MCAN调试协议）";
CM_ SG_ 2416045693 S2P_DIAG_BYTE6_61 "SBMU发送到PC的诊断报文（详见SBMU MCAN调试协议）";
CM_ SG_ 2416045693 S2P_DIAG_BYTE7_61 "SBMU发送到PC的诊断报文（详见SBMU MCAN调试协议）";
CM_ SG_ 2416045693 S2P_DIAG_BYTE8_61 "SBMU发送到PC的诊断报文（详见SBMU MCAN调试协议）";
CM_ SG_ 2416045694 S2P_DIAG_BYTE1_62 "SBMU发送到PC的诊断报文（详见SBMU MCAN调试协议）";
CM_ SG_ 2416045694 S2P_DIAG_BYTE2_62 "SBMU发送到PC的诊断报文（详见SBMU MCAN调试协议）";
CM_ SG_ 2416045694 S2P_DIAG_BYTE3_62 "SBMU发送到PC的诊断报文（详见SBMU MCAN调试协议）";
CM_ SG_ 2416045694 S2P_DIAG_BYTE4_62 "SBMU发送到PC的诊断报文（详见SBMU MCAN调试协议）";
CM_ SG_ 2416045694 S2P_DIAG_BYTE5_62 "SBMU发送到PC的诊断报文（详见SBMU MCAN调试协议）";
CM_ SG_ 2416045694 S2P_DIAG_BYTE6_62 "SBMU发送到PC的诊断报文（详见SBMU MCAN调试协议）";
CM_ SG_ 2416045694 S2P_DIAG_BYTE7_62 "SBMU发送到PC的诊断报文（详见SBMU MCAN调试协议）";
CM_ SG_ 2416045694 S2P_DIAG_BYTE8_62 "SBMU发送到PC的诊断报文（详见SBMU MCAN调试协议）";
CM_ SG_ 2416045695 S2P_DIAG_BYTE1_63 "SBMU发送到PC的诊断报文（详见SBMU MCAN调试协议）";
CM_ SG_ 2416045695 S2P_DIAG_BYTE2_63 "SBMU发送到PC的诊断报文（详见SBMU MCAN调试协议）";
CM_ SG_ 2416045695 S2P_DIAG_BYTE3_63 "SBMU发送到PC的诊断报文（详见SBMU MCAN调试协议）";
CM_ SG_ 2416045695 S2P_DIAG_BYTE4_63 "SBMU发送到PC的诊断报文（详见SBMU MCAN调试协议）";
CM_ SG_ 2416045695 S2P_DIAG_BYTE5_63 "SBMU发送到PC的诊断报文（详见SBMU MCAN调试协议）";
CM_ SG_ 2416045695 S2P_DIAG_BYTE6_63 "SBMU发送到PC的诊断报文（详见SBMU MCAN调试协议）";
CM_ SG_ 2416045695 S2P_DIAG_BYTE7_63 "SBMU发送到PC的诊断报文（详见SBMU MCAN调试协议）";
CM_ SG_ 2416045695 S2P_DIAG_BYTE8_63 "SBMU发送到PC的诊断报文（详见SBMU MCAN调试协议）";
CM_ SG_ 2416111169 S2P_Cfg1_SW_Ver_Byte1_01 "SBMU软件版本号最低字节Byte1对应的ASCII码";
CM_ SG_ 2416111169 S2P_Cfg1_SW_Ver_Byte2_01 "SBMU软件版本号Byte2对应的ASCII码";
CM_ SG_ 2416111169 S2P_Cfg1_SW_Ver_Byte3_01 "SBMU软件版本号Byte3对应的ASCII码";
CM_ SG_ 2416111169 S2P_Cfg1_SW_Ver_Byte4_01 "SBMU软件版本号Byte4对应的ASCII码";
CM_ SG_ 2416111169 S2P_Cfg1_SW_Ver_Byte5_01 "SBMU软件版本号Byte5对应的ASCII码";
CM_ SG_ 2416111169 S2P_Cfg1_SW_Ver_Byte6_01 "SBMU软件版本号Byte6对应的ASCII码";
CM_ SG_ 2416111169 S2P_Cfg1_SW_Ver_Byte7_01 "SBMU软件版本号Byte7对应的ASCII码";
CM_ SG_ 2416111169 S2P_Cfg1_SW_Ver_Byte8_01 "SBMU软件版本号Byte8对应的ASCII码";
CM_ SG_ 2416111170 S2P_Cfg1_SW_Ver_Byte1_02 "SBMU软件版本号最低字节Byte1对应的ASCII码";
CM_ SG_ 2416111170 S2P_Cfg1_SW_Ver_Byte2_02 "SBMU软件版本号Byte2对应的ASCII码";
CM_ SG_ 2416111170 S2P_Cfg1_SW_Ver_Byte3_02 "SBMU软件版本号Byte3对应的ASCII码";
CM_ SG_ 2416111170 S2P_Cfg1_SW_Ver_Byte4_02 "SBMU软件版本号Byte4对应的ASCII码";
CM_ SG_ 2416111170 S2P_Cfg1_SW_Ver_Byte5_02 "SBMU软件版本号Byte5对应的ASCII码";
CM_ SG_ 2416111170 S2P_Cfg1_SW_Ver_Byte6_02 "SBMU软件版本号Byte6对应的ASCII码";
CM_ SG_ 2416111170 S2P_Cfg1_SW_Ver_Byte7_02 "SBMU软件版本号Byte7对应的ASCII码";
CM_ SG_ 2416111170 S2P_Cfg1_SW_Ver_Byte8_02 "SBMU软件版本号Byte8对应的ASCII码";
CM_ SG_ 2416111171 S2P_Cfg1_SW_Ver_Byte1_03 "SBMU软件版本号最低字节Byte1对应的ASCII码";
CM_ SG_ 2416111171 S2P_Cfg1_SW_Ver_Byte2_03 "SBMU软件版本号Byte2对应的ASCII码";
CM_ SG_ 2416111171 S2P_Cfg1_SW_Ver_Byte3_03 "SBMU软件版本号Byte3对应的ASCII码";
CM_ SG_ 2416111171 S2P_Cfg1_SW_Ver_Byte4_03 "SBMU软件版本号Byte4对应的ASCII码";
CM_ SG_ 2416111171 S2P_Cfg1_SW_Ver_Byte5_03 "SBMU软件版本号Byte5对应的ASCII码";
CM_ SG_ 2416111171 S2P_Cfg1_SW_Ver_Byte6_03 "SBMU软件版本号Byte6对应的ASCII码";
CM_ SG_ 2416111171 S2P_Cfg1_SW_Ver_Byte7_03 "SBMU软件版本号Byte7对应的ASCII码";
CM_ SG_ 2416111171 S2P_Cfg1_SW_Ver_Byte8_03 "SBMU软件版本号Byte8对应的ASCII码";
CM_ SG_ 2416111172 S2P_Cfg1_SW_Ver_Byte1_04 "SBMU软件版本号最低字节Byte1对应的ASCII码";
CM_ SG_ 2416111172 S2P_Cfg1_SW_Ver_Byte2_04 "SBMU软件版本号Byte2对应的ASCII码";
CM_ SG_ 2416111172 S2P_Cfg1_SW_Ver_Byte3_04 "SBMU软件版本号Byte3对应的ASCII码";
CM_ SG_ 2416111172 S2P_Cfg1_SW_Ver_Byte4_04 "SBMU软件版本号Byte4对应的ASCII码";
CM_ SG_ 2416111172 S2P_Cfg1_SW_Ver_Byte5_04 "SBMU软件版本号Byte5对应的ASCII码";
CM_ SG_ 2416111172 S2P_Cfg1_SW_Ver_Byte6_04 "SBMU软件版本号Byte6对应的ASCII码";
CM_ SG_ 2416111172 S2P_Cfg1_SW_Ver_Byte7_04 "SBMU软件版本号Byte7对应的ASCII码";
CM_ SG_ 2416111172 S2P_Cfg1_SW_Ver_Byte8_04 "SBMU软件版本号Byte8对应的ASCII码";
CM_ SG_ 2416111173 S2P_Cfg1_SW_Ver_Byte1_05 "SBMU软件版本号最低字节Byte1对应的ASCII码";
CM_ SG_ 2416111173 S2P_Cfg1_SW_Ver_Byte2_05 "SBMU软件版本号Byte2对应的ASCII码";
CM_ SG_ 2416111173 S2P_Cfg1_SW_Ver_Byte3_05 "SBMU软件版本号Byte3对应的ASCII码";
CM_ SG_ 2416111173 S2P_Cfg1_SW_Ver_Byte4_05 "SBMU软件版本号Byte4对应的ASCII码";
CM_ SG_ 2416111173 S2P_Cfg1_SW_Ver_Byte5_05 "SBMU软件版本号Byte5对应的ASCII码";
CM_ SG_ 2416111173 S2P_Cfg1_SW_Ver_Byte6_05 "SBMU软件版本号Byte6对应的ASCII码";
CM_ SG_ 2416111173 S2P_Cfg1_SW_Ver_Byte7_05 "SBMU软件版本号Byte7对应的ASCII码";
CM_ SG_ 2416111173 S2P_Cfg1_SW_Ver_Byte8_05 "SBMU软件版本号Byte8对应的ASCII码";
CM_ SG_ 2416111174 S2P_Cfg1_SW_Ver_Byte1_06 "SBMU软件版本号最低字节Byte1对应的ASCII码";
CM_ SG_ 2416111174 S2P_Cfg1_SW_Ver_Byte2_06 "SBMU软件版本号Byte2对应的ASCII码";
CM_ SG_ 2416111174 S2P_Cfg1_SW_Ver_Byte3_06 "SBMU软件版本号Byte3对应的ASCII码";
CM_ SG_ 2416111174 S2P_Cfg1_SW_Ver_Byte4_06 "SBMU软件版本号Byte4对应的ASCII码";
CM_ SG_ 2416111174 S2P_Cfg1_SW_Ver_Byte5_06 "SBMU软件版本号Byte5对应的ASCII码";
CM_ SG_ 2416111174 S2P_Cfg1_SW_Ver_Byte6_06 "SBMU软件版本号Byte6对应的ASCII码";
CM_ SG_ 2416111174 S2P_Cfg1_SW_Ver_Byte7_06 "SBMU软件版本号Byte7对应的ASCII码";
CM_ SG_ 2416111174 S2P_Cfg1_SW_Ver_Byte8_06 "SBMU软件版本号Byte8对应的ASCII码";
CM_ SG_ 2416111175 S2P_Cfg1_SW_Ver_Byte1_07 "SBMU软件版本号最低字节Byte1对应的ASCII码";
CM_ SG_ 2416111175 S2P_Cfg1_SW_Ver_Byte2_07 "SBMU软件版本号Byte2对应的ASCII码";
CM_ SG_ 2416111175 S2P_Cfg1_SW_Ver_Byte3_07 "SBMU软件版本号Byte3对应的ASCII码";
CM_ SG_ 2416111175 S2P_Cfg1_SW_Ver_Byte4_07 "SBMU软件版本号Byte4对应的ASCII码";
CM_ SG_ 2416111175 S2P_Cfg1_SW_Ver_Byte5_07 "SBMU软件版本号Byte5对应的ASCII码";
CM_ SG_ 2416111175 S2P_Cfg1_SW_Ver_Byte6_07 "SBMU软件版本号Byte6对应的ASCII码";
CM_ SG_ 2416111175 S2P_Cfg1_SW_Ver_Byte7_07 "SBMU软件版本号Byte7对应的ASCII码";
CM_ SG_ 2416111175 S2P_Cfg1_SW_Ver_Byte8_07 "SBMU软件版本号Byte8对应的ASCII码";
CM_ SG_ 2416111176 S2P_Cfg1_SW_Ver_Byte1_08 "SBMU软件版本号最低字节Byte1对应的ASCII码";
CM_ SG_ 2416111176 S2P_Cfg1_SW_Ver_Byte2_08 "SBMU软件版本号Byte2对应的ASCII码";
CM_ SG_ 2416111176 S2P_Cfg1_SW_Ver_Byte3_08 "SBMU软件版本号Byte3对应的ASCII码";
CM_ SG_ 2416111176 S2P_Cfg1_SW_Ver_Byte4_08 "SBMU软件版本号Byte4对应的ASCII码";
CM_ SG_ 2416111176 S2P_Cfg1_SW_Ver_Byte5_08 "SBMU软件版本号Byte5对应的ASCII码";
CM_ SG_ 2416111176 S2P_Cfg1_SW_Ver_Byte6_08 "SBMU软件版本号Byte6对应的ASCII码";
CM_ SG_ 2416111176 S2P_Cfg1_SW_Ver_Byte7_08 "SBMU软件版本号Byte7对应的ASCII码";
CM_ SG_ 2416111176 S2P_Cfg1_SW_Ver_Byte8_08 "SBMU软件版本号Byte8对应的ASCII码";
CM_ SG_ 2416111177 S2P_Cfg1_SW_Ver_Byte1_09 "SBMU软件版本号最低字节Byte1对应的ASCII码";
CM_ SG_ 2416111177 S2P_Cfg1_SW_Ver_Byte2_09 "SBMU软件版本号Byte2对应的ASCII码";
CM_ SG_ 2416111177 S2P_Cfg1_SW_Ver_Byte3_09 "SBMU软件版本号Byte3对应的ASCII码";
CM_ SG_ 2416111177 S2P_Cfg1_SW_Ver_Byte4_09 "SBMU软件版本号Byte4对应的ASCII码";
CM_ SG_ 2416111177 S2P_Cfg1_SW_Ver_Byte5_09 "SBMU软件版本号Byte5对应的ASCII码";
CM_ SG_ 2416111177 S2P_Cfg1_SW_Ver_Byte6_09 "SBMU软件版本号Byte6对应的ASCII码";
CM_ SG_ 2416111177 S2P_Cfg1_SW_Ver_Byte7_09 "SBMU软件版本号Byte7对应的ASCII码";
CM_ SG_ 2416111177 S2P_Cfg1_SW_Ver_Byte8_09 "SBMU软件版本号Byte8对应的ASCII码";
CM_ SG_ 2416111178 S2P_Cfg1_SW_Ver_Byte1_10 "SBMU软件版本号最低字节Byte1对应的ASCII码";
CM_ SG_ 2416111178 S2P_Cfg1_SW_Ver_Byte2_10 "SBMU软件版本号Byte2对应的ASCII码";
CM_ SG_ 2416111178 S2P_Cfg1_SW_Ver_Byte3_10 "SBMU软件版本号Byte3对应的ASCII码";
CM_ SG_ 2416111178 S2P_Cfg1_SW_Ver_Byte4_10 "SBMU软件版本号Byte4对应的ASCII码";
CM_ SG_ 2416111178 S2P_Cfg1_SW_Ver_Byte5_10 "SBMU软件版本号Byte5对应的ASCII码";
CM_ SG_ 2416111178 S2P_Cfg1_SW_Ver_Byte6_10 "SBMU软件版本号Byte6对应的ASCII码";
CM_ SG_ 2416111178 S2P_Cfg1_SW_Ver_Byte7_10 "SBMU软件版本号Byte7对应的ASCII码";
CM_ SG_ 2416111178 S2P_Cfg1_SW_Ver_Byte8_10 "SBMU软件版本号Byte8对应的ASCII码";
CM_ SG_ 2416111179 S2P_Cfg1_SW_Ver_Byte1_11 "SBMU软件版本号最低字节Byte1对应的ASCII码";
CM_ SG_ 2416111179 S2P_Cfg1_SW_Ver_Byte2_11 "SBMU软件版本号Byte2对应的ASCII码";
CM_ SG_ 2416111179 S2P_Cfg1_SW_Ver_Byte3_11 "SBMU软件版本号Byte3对应的ASCII码";
CM_ SG_ 2416111179 S2P_Cfg1_SW_Ver_Byte4_11 "SBMU软件版本号Byte4对应的ASCII码";
CM_ SG_ 2416111179 S2P_Cfg1_SW_Ver_Byte5_11 "SBMU软件版本号Byte5对应的ASCII码";
CM_ SG_ 2416111179 S2P_Cfg1_SW_Ver_Byte6_11 "SBMU软件版本号Byte6对应的ASCII码";
CM_ SG_ 2416111179 S2P_Cfg1_SW_Ver_Byte7_11 "SBMU软件版本号Byte7对应的ASCII码";
CM_ SG_ 2416111179 S2P_Cfg1_SW_Ver_Byte8_11 "SBMU软件版本号Byte8对应的ASCII码";
CM_ SG_ 2416111180 S2P_Cfg1_SW_Ver_Byte1_12 "SBMU软件版本号最低字节Byte1对应的ASCII码";
CM_ SG_ 2416111180 S2P_Cfg1_SW_Ver_Byte2_12 "SBMU软件版本号Byte2对应的ASCII码";
CM_ SG_ 2416111180 S2P_Cfg1_SW_Ver_Byte3_12 "SBMU软件版本号Byte3对应的ASCII码";
CM_ SG_ 2416111180 S2P_Cfg1_SW_Ver_Byte4_12 "SBMU软件版本号Byte4对应的ASCII码";
CM_ SG_ 2416111180 S2P_Cfg1_SW_Ver_Byte5_12 "SBMU软件版本号Byte5对应的ASCII码";
CM_ SG_ 2416111180 S2P_Cfg1_SW_Ver_Byte6_12 "SBMU软件版本号Byte6对应的ASCII码";
CM_ SG_ 2416111180 S2P_Cfg1_SW_Ver_Byte7_12 "SBMU软件版本号Byte7对应的ASCII码";
CM_ SG_ 2416111180 S2P_Cfg1_SW_Ver_Byte8_12 "SBMU软件版本号Byte8对应的ASCII码";
CM_ SG_ 2416111181 S2P_Cfg1_SW_Ver_Byte1_13 "SBMU软件版本号最低字节Byte1对应的ASCII码";
CM_ SG_ 2416111181 S2P_Cfg1_SW_Ver_Byte2_13 "SBMU软件版本号Byte2对应的ASCII码";
CM_ SG_ 2416111181 S2P_Cfg1_SW_Ver_Byte3_13 "SBMU软件版本号Byte3对应的ASCII码";
CM_ SG_ 2416111181 S2P_Cfg1_SW_Ver_Byte4_13 "SBMU软件版本号Byte4对应的ASCII码";
CM_ SG_ 2416111181 S2P_Cfg1_SW_Ver_Byte5_13 "SBMU软件版本号Byte5对应的ASCII码";
CM_ SG_ 2416111181 S2P_Cfg1_SW_Ver_Byte6_13 "SBMU软件版本号Byte6对应的ASCII码";
CM_ SG_ 2416111181 S2P_Cfg1_SW_Ver_Byte7_13 "SBMU软件版本号Byte7对应的ASCII码";
CM_ SG_ 2416111181 S2P_Cfg1_SW_Ver_Byte8_13 "SBMU软件版本号Byte8对应的ASCII码";
CM_ SG_ 2416111182 S2P_Cfg1_SW_Ver_Byte1_14 "SBMU软件版本号最低字节Byte1对应的ASCII码";
CM_ SG_ 2416111182 S2P_Cfg1_SW_Ver_Byte2_14 "SBMU软件版本号Byte2对应的ASCII码";
CM_ SG_ 2416111182 S2P_Cfg1_SW_Ver_Byte3_14 "SBMU软件版本号Byte3对应的ASCII码";
CM_ SG_ 2416111182 S2P_Cfg1_SW_Ver_Byte4_14 "SBMU软件版本号Byte4对应的ASCII码";
CM_ SG_ 2416111182 S2P_Cfg1_SW_Ver_Byte5_14 "SBMU软件版本号Byte5对应的ASCII码";
CM_ SG_ 2416111182 S2P_Cfg1_SW_Ver_Byte6_14 "SBMU软件版本号Byte6对应的ASCII码";
CM_ SG_ 2416111182 S2P_Cfg1_SW_Ver_Byte7_14 "SBMU软件版本号Byte7对应的ASCII码";
CM_ SG_ 2416111182 S2P_Cfg1_SW_Ver_Byte8_14 "SBMU软件版本号Byte8对应的ASCII码";
CM_ SG_ 2416111183 S2P_Cfg1_SW_Ver_Byte1_15 "SBMU软件版本号最低字节Byte1对应的ASCII码";
CM_ SG_ 2416111183 S2P_Cfg1_SW_Ver_Byte2_15 "SBMU软件版本号Byte2对应的ASCII码";
CM_ SG_ 2416111183 S2P_Cfg1_SW_Ver_Byte3_15 "SBMU软件版本号Byte3对应的ASCII码";
CM_ SG_ 2416111183 S2P_Cfg1_SW_Ver_Byte4_15 "SBMU软件版本号Byte4对应的ASCII码";
CM_ SG_ 2416111183 S2P_Cfg1_SW_Ver_Byte5_15 "SBMU软件版本号Byte5对应的ASCII码";
CM_ SG_ 2416111183 S2P_Cfg1_SW_Ver_Byte6_15 "SBMU软件版本号Byte6对应的ASCII码";
CM_ SG_ 2416111183 S2P_Cfg1_SW_Ver_Byte7_15 "SBMU软件版本号Byte7对应的ASCII码";
CM_ SG_ 2416111183 S2P_Cfg1_SW_Ver_Byte8_15 "SBMU软件版本号Byte8对应的ASCII码";
CM_ SG_ 2416111184 S2P_Cfg1_SW_Ver_Byte1_16 "SBMU软件版本号最低字节Byte1对应的ASCII码";
CM_ SG_ 2416111184 S2P_Cfg1_SW_Ver_Byte2_16 "SBMU软件版本号Byte2对应的ASCII码";
CM_ SG_ 2416111184 S2P_Cfg1_SW_Ver_Byte3_16 "SBMU软件版本号Byte3对应的ASCII码";
CM_ SG_ 2416111184 S2P_Cfg1_SW_Ver_Byte4_16 "SBMU软件版本号Byte4对应的ASCII码";
CM_ SG_ 2416111184 S2P_Cfg1_SW_Ver_Byte5_16 "SBMU软件版本号Byte5对应的ASCII码";
CM_ SG_ 2416111184 S2P_Cfg1_SW_Ver_Byte6_16 "SBMU软件版本号Byte6对应的ASCII码";
CM_ SG_ 2416111184 S2P_Cfg1_SW_Ver_Byte7_16 "SBMU软件版本号Byte7对应的ASCII码";
CM_ SG_ 2416111184 S2P_Cfg1_SW_Ver_Byte8_16 "SBMU软件版本号Byte8对应的ASCII码";
CM_ SG_ 2416111185 S2P_Cfg1_SW_Ver_Byte1_17 "SBMU软件版本号最低字节Byte1对应的ASCII码";
CM_ SG_ 2416111185 S2P_Cfg1_SW_Ver_Byte2_17 "SBMU软件版本号Byte2对应的ASCII码";
CM_ SG_ 2416111185 S2P_Cfg1_SW_Ver_Byte3_17 "SBMU软件版本号Byte3对应的ASCII码";
CM_ SG_ 2416111185 S2P_Cfg1_SW_Ver_Byte4_17 "SBMU软件版本号Byte4对应的ASCII码";
CM_ SG_ 2416111185 S2P_Cfg1_SW_Ver_Byte5_17 "SBMU软件版本号Byte5对应的ASCII码";
CM_ SG_ 2416111185 S2P_Cfg1_SW_Ver_Byte6_17 "SBMU软件版本号Byte6对应的ASCII码";
CM_ SG_ 2416111185 S2P_Cfg1_SW_Ver_Byte7_17 "SBMU软件版本号Byte7对应的ASCII码";
CM_ SG_ 2416111185 S2P_Cfg1_SW_Ver_Byte8_17 "SBMU软件版本号Byte8对应的ASCII码";
CM_ SG_ 2416111186 S2P_Cfg1_SW_Ver_Byte1_18 "SBMU软件版本号最低字节Byte1对应的ASCII码";
CM_ SG_ 2416111186 S2P_Cfg1_SW_Ver_Byte2_18 "SBMU软件版本号Byte2对应的ASCII码";
CM_ SG_ 2416111186 S2P_Cfg1_SW_Ver_Byte3_18 "SBMU软件版本号Byte3对应的ASCII码";
CM_ SG_ 2416111186 S2P_Cfg1_SW_Ver_Byte4_18 "SBMU软件版本号Byte4对应的ASCII码";
CM_ SG_ 2416111186 S2P_Cfg1_SW_Ver_Byte5_18 "SBMU软件版本号Byte5对应的ASCII码";
CM_ SG_ 2416111186 S2P_Cfg1_SW_Ver_Byte6_18 "SBMU软件版本号Byte6对应的ASCII码";
CM_ SG_ 2416111186 S2P_Cfg1_SW_Ver_Byte7_18 "SBMU软件版本号Byte7对应的ASCII码";
CM_ SG_ 2416111186 S2P_Cfg1_SW_Ver_Byte8_18 "SBMU软件版本号Byte8对应的ASCII码";
CM_ SG_ 2416111187 S2P_Cfg1_SW_Ver_Byte1_19 "SBMU软件版本号最低字节Byte1对应的ASCII码";
CM_ SG_ 2416111187 S2P_Cfg1_SW_Ver_Byte2_19 "SBMU软件版本号Byte2对应的ASCII码";
CM_ SG_ 2416111187 S2P_Cfg1_SW_Ver_Byte3_19 "SBMU软件版本号Byte3对应的ASCII码";
CM_ SG_ 2416111187 S2P_Cfg1_SW_Ver_Byte4_19 "SBMU软件版本号Byte4对应的ASCII码";
CM_ SG_ 2416111187 S2P_Cfg1_SW_Ver_Byte5_19 "SBMU软件版本号Byte5对应的ASCII码";
CM_ SG_ 2416111187 S2P_Cfg1_SW_Ver_Byte6_19 "SBMU软件版本号Byte6对应的ASCII码";
CM_ SG_ 2416111187 S2P_Cfg1_SW_Ver_Byte7_19 "SBMU软件版本号Byte7对应的ASCII码";
CM_ SG_ 2416111187 S2P_Cfg1_SW_Ver_Byte8_19 "SBMU软件版本号Byte8对应的ASCII码";
CM_ SG_ 2416111188 S2P_Cfg1_SW_Ver_Byte1_20 "SBMU软件版本号最低字节Byte1对应的ASCII码";
CM_ SG_ 2416111188 S2P_Cfg1_SW_Ver_Byte2_20 "SBMU软件版本号Byte2对应的ASCII码";
CM_ SG_ 2416111188 S2P_Cfg1_SW_Ver_Byte3_20 "SBMU软件版本号Byte3对应的ASCII码";
CM_ SG_ 2416111188 S2P_Cfg1_SW_Ver_Byte4_20 "SBMU软件版本号Byte4对应的ASCII码";
CM_ SG_ 2416111188 S2P_Cfg1_SW_Ver_Byte5_20 "SBMU软件版本号Byte5对应的ASCII码";
CM_ SG_ 2416111188 S2P_Cfg1_SW_Ver_Byte6_20 "SBMU软件版本号Byte6对应的ASCII码";
CM_ SG_ 2416111188 S2P_Cfg1_SW_Ver_Byte7_20 "SBMU软件版本号Byte7对应的ASCII码";
CM_ SG_ 2416111188 S2P_Cfg1_SW_Ver_Byte8_20 "SBMU软件版本号Byte8对应的ASCII码";
CM_ SG_ 2416111189 S2P_Cfg1_SW_Ver_Byte1_21 "SBMU软件版本号最低字节Byte1对应的ASCII码";
CM_ SG_ 2416111189 S2P_Cfg1_SW_Ver_Byte2_21 "SBMU软件版本号Byte2对应的ASCII码";
CM_ SG_ 2416111189 S2P_Cfg1_SW_Ver_Byte3_21 "SBMU软件版本号Byte3对应的ASCII码";
CM_ SG_ 2416111189 S2P_Cfg1_SW_Ver_Byte4_21 "SBMU软件版本号Byte4对应的ASCII码";
CM_ SG_ 2416111189 S2P_Cfg1_SW_Ver_Byte5_21 "SBMU软件版本号Byte5对应的ASCII码";
CM_ SG_ 2416111189 S2P_Cfg1_SW_Ver_Byte6_21 "SBMU软件版本号Byte6对应的ASCII码";
CM_ SG_ 2416111189 S2P_Cfg1_SW_Ver_Byte7_21 "SBMU软件版本号Byte7对应的ASCII码";
CM_ SG_ 2416111189 S2P_Cfg1_SW_Ver_Byte8_21 "SBMU软件版本号Byte8对应的ASCII码";
CM_ SG_ 2416111190 S2P_Cfg1_SW_Ver_Byte1_22 "SBMU软件版本号最低字节Byte1对应的ASCII码";
CM_ SG_ 2416111190 S2P_Cfg1_SW_Ver_Byte2_22 "SBMU软件版本号Byte2对应的ASCII码";
CM_ SG_ 2416111190 S2P_Cfg1_SW_Ver_Byte3_22 "SBMU软件版本号Byte3对应的ASCII码";
CM_ SG_ 2416111190 S2P_Cfg1_SW_Ver_Byte4_22 "SBMU软件版本号Byte4对应的ASCII码";
CM_ SG_ 2416111190 S2P_Cfg1_SW_Ver_Byte5_22 "SBMU软件版本号Byte5对应的ASCII码";
CM_ SG_ 2416111190 S2P_Cfg1_SW_Ver_Byte6_22 "SBMU软件版本号Byte6对应的ASCII码";
CM_ SG_ 2416111190 S2P_Cfg1_SW_Ver_Byte7_22 "SBMU软件版本号Byte7对应的ASCII码";
CM_ SG_ 2416111190 S2P_Cfg1_SW_Ver_Byte8_22 "SBMU软件版本号Byte8对应的ASCII码";
CM_ SG_ 2416111191 S2P_Cfg1_SW_Ver_Byte1_23 "SBMU软件版本号最低字节Byte1对应的ASCII码";
CM_ SG_ 2416111191 S2P_Cfg1_SW_Ver_Byte2_23 "SBMU软件版本号Byte2对应的ASCII码";
CM_ SG_ 2416111191 S2P_Cfg1_SW_Ver_Byte3_23 "SBMU软件版本号Byte3对应的ASCII码";
CM_ SG_ 2416111191 S2P_Cfg1_SW_Ver_Byte4_23 "SBMU软件版本号Byte4对应的ASCII码";
CM_ SG_ 2416111191 S2P_Cfg1_SW_Ver_Byte5_23 "SBMU软件版本号Byte5对应的ASCII码";
CM_ SG_ 2416111191 S2P_Cfg1_SW_Ver_Byte6_23 "SBMU软件版本号Byte6对应的ASCII码";
CM_ SG_ 2416111191 S2P_Cfg1_SW_Ver_Byte7_23 "SBMU软件版本号Byte7对应的ASCII码";
CM_ SG_ 2416111191 S2P_Cfg1_SW_Ver_Byte8_23 "SBMU软件版本号Byte8对应的ASCII码";
CM_ SG_ 2416111192 S2P_Cfg1_SW_Ver_Byte1_24 "SBMU软件版本号最低字节Byte1对应的ASCII码";
CM_ SG_ 2416111192 S2P_Cfg1_SW_Ver_Byte2_24 "SBMU软件版本号Byte2对应的ASCII码";
CM_ SG_ 2416111192 S2P_Cfg1_SW_Ver_Byte3_24 "SBMU软件版本号Byte3对应的ASCII码";
CM_ SG_ 2416111192 S2P_Cfg1_SW_Ver_Byte4_24 "SBMU软件版本号Byte4对应的ASCII码";
CM_ SG_ 2416111192 S2P_Cfg1_SW_Ver_Byte5_24 "SBMU软件版本号Byte5对应的ASCII码";
CM_ SG_ 2416111192 S2P_Cfg1_SW_Ver_Byte6_24 "SBMU软件版本号Byte6对应的ASCII码";
CM_ SG_ 2416111192 S2P_Cfg1_SW_Ver_Byte7_24 "SBMU软件版本号Byte7对应的ASCII码";
CM_ SG_ 2416111192 S2P_Cfg1_SW_Ver_Byte8_24 "SBMU软件版本号Byte8对应的ASCII码";
CM_ SG_ 2416111193 S2P_Cfg1_SW_Ver_Byte1_25 "SBMU软件版本号最低字节Byte1对应的ASCII码";
CM_ SG_ 2416111193 S2P_Cfg1_SW_Ver_Byte2_25 "SBMU软件版本号Byte2对应的ASCII码";
CM_ SG_ 2416111193 S2P_Cfg1_SW_Ver_Byte3_25 "SBMU软件版本号Byte3对应的ASCII码";
CM_ SG_ 2416111193 S2P_Cfg1_SW_Ver_Byte4_25 "SBMU软件版本号Byte4对应的ASCII码";
CM_ SG_ 2416111193 S2P_Cfg1_SW_Ver_Byte5_25 "SBMU软件版本号Byte5对应的ASCII码";
CM_ SG_ 2416111193 S2P_Cfg1_SW_Ver_Byte6_25 "SBMU软件版本号Byte6对应的ASCII码";
CM_ SG_ 2416111193 S2P_Cfg1_SW_Ver_Byte7_25 "SBMU软件版本号Byte7对应的ASCII码";
CM_ SG_ 2416111193 S2P_Cfg1_SW_Ver_Byte8_25 "SBMU软件版本号Byte8对应的ASCII码";
CM_ SG_ 2416111194 S2P_Cfg1_SW_Ver_Byte1_26 "SBMU软件版本号最低字节Byte1对应的ASCII码";
CM_ SG_ 2416111194 S2P_Cfg1_SW_Ver_Byte2_26 "SBMU软件版本号Byte2对应的ASCII码";
CM_ SG_ 2416111194 S2P_Cfg1_SW_Ver_Byte3_26 "SBMU软件版本号Byte3对应的ASCII码";
CM_ SG_ 2416111194 S2P_Cfg1_SW_Ver_Byte4_26 "SBMU软件版本号Byte4对应的ASCII码";
CM_ SG_ 2416111194 S2P_Cfg1_SW_Ver_Byte5_26 "SBMU软件版本号Byte5对应的ASCII码";
CM_ SG_ 2416111194 S2P_Cfg1_SW_Ver_Byte6_26 "SBMU软件版本号Byte6对应的ASCII码";
CM_ SG_ 2416111194 S2P_Cfg1_SW_Ver_Byte7_26 "SBMU软件版本号Byte7对应的ASCII码";
CM_ SG_ 2416111194 S2P_Cfg1_SW_Ver_Byte8_26 "SBMU软件版本号Byte8对应的ASCII码";
CM_ SG_ 2416111195 S2P_Cfg1_SW_Ver_Byte1_27 "SBMU软件版本号最低字节Byte1对应的ASCII码";
CM_ SG_ 2416111195 S2P_Cfg1_SW_Ver_Byte2_27 "SBMU软件版本号Byte2对应的ASCII码";
CM_ SG_ 2416111195 S2P_Cfg1_SW_Ver_Byte3_27 "SBMU软件版本号Byte3对应的ASCII码";
CM_ SG_ 2416111195 S2P_Cfg1_SW_Ver_Byte4_27 "SBMU软件版本号Byte4对应的ASCII码";
CM_ SG_ 2416111195 S2P_Cfg1_SW_Ver_Byte5_27 "SBMU软件版本号Byte5对应的ASCII码";
CM_ SG_ 2416111195 S2P_Cfg1_SW_Ver_Byte6_27 "SBMU软件版本号Byte6对应的ASCII码";
CM_ SG_ 2416111195 S2P_Cfg1_SW_Ver_Byte7_27 "SBMU软件版本号Byte7对应的ASCII码";
CM_ SG_ 2416111195 S2P_Cfg1_SW_Ver_Byte8_27 "SBMU软件版本号Byte8对应的ASCII码";
CM_ SG_ 2416111196 S2P_Cfg1_SW_Ver_Byte1_28 "SBMU软件版本号最低字节Byte1对应的ASCII码";
CM_ SG_ 2416111196 S2P_Cfg1_SW_Ver_Byte2_28 "SBMU软件版本号Byte2对应的ASCII码";
CM_ SG_ 2416111196 S2P_Cfg1_SW_Ver_Byte3_28 "SBMU软件版本号Byte3对应的ASCII码";
CM_ SG_ 2416111196 S2P_Cfg1_SW_Ver_Byte4_28 "SBMU软件版本号Byte4对应的ASCII码";
CM_ SG_ 2416111196 S2P_Cfg1_SW_Ver_Byte5_28 "SBMU软件版本号Byte5对应的ASCII码";
CM_ SG_ 2416111196 S2P_Cfg1_SW_Ver_Byte6_28 "SBMU软件版本号Byte6对应的ASCII码";
CM_ SG_ 2416111196 S2P_Cfg1_SW_Ver_Byte7_28 "SBMU软件版本号Byte7对应的ASCII码";
CM_ SG_ 2416111196 S2P_Cfg1_SW_Ver_Byte8_28 "SBMU软件版本号Byte8对应的ASCII码";
CM_ SG_ 2416111197 S2P_Cfg1_SW_Ver_Byte1_29 "SBMU软件版本号最低字节Byte1对应的ASCII码";
CM_ SG_ 2416111197 S2P_Cfg1_SW_Ver_Byte2_29 "SBMU软件版本号Byte2对应的ASCII码";
CM_ SG_ 2416111197 S2P_Cfg1_SW_Ver_Byte3_29 "SBMU软件版本号Byte3对应的ASCII码";
CM_ SG_ 2416111197 S2P_Cfg1_SW_Ver_Byte4_29 "SBMU软件版本号Byte4对应的ASCII码";
CM_ SG_ 2416111197 S2P_Cfg1_SW_Ver_Byte5_29 "SBMU软件版本号Byte5对应的ASCII码";
CM_ SG_ 2416111197 S2P_Cfg1_SW_Ver_Byte6_29 "SBMU软件版本号Byte6对应的ASCII码";
CM_ SG_ 2416111197 S2P_Cfg1_SW_Ver_Byte7_29 "SBMU软件版本号Byte7对应的ASCII码";
CM_ SG_ 2416111197 S2P_Cfg1_SW_Ver_Byte8_29 "SBMU软件版本号Byte8对应的ASCII码";
CM_ SG_ 2416111198 S2P_Cfg1_SW_Ver_Byte1_30 "SBMU软件版本号最低字节Byte1对应的ASCII码";
CM_ SG_ 2416111198 S2P_Cfg1_SW_Ver_Byte2_30 "SBMU软件版本号Byte2对应的ASCII码";
CM_ SG_ 2416111198 S2P_Cfg1_SW_Ver_Byte3_30 "SBMU软件版本号Byte3对应的ASCII码";
CM_ SG_ 2416111198 S2P_Cfg1_SW_Ver_Byte4_30 "SBMU软件版本号Byte4对应的ASCII码";
CM_ SG_ 2416111198 S2P_Cfg1_SW_Ver_Byte5_30 "SBMU软件版本号Byte5对应的ASCII码";
CM_ SG_ 2416111198 S2P_Cfg1_SW_Ver_Byte6_30 "SBMU软件版本号Byte6对应的ASCII码";
CM_ SG_ 2416111198 S2P_Cfg1_SW_Ver_Byte7_30 "SBMU软件版本号Byte7对应的ASCII码";
CM_ SG_ 2416111198 S2P_Cfg1_SW_Ver_Byte8_30 "SBMU软件版本号Byte8对应的ASCII码";
CM_ SG_ 2416111199 S2P_Cfg1_SW_Ver_Byte1_31 "SBMU软件版本号最低字节Byte1对应的ASCII码";
CM_ SG_ 2416111199 S2P_Cfg1_SW_Ver_Byte2_31 "SBMU软件版本号Byte2对应的ASCII码";
CM_ SG_ 2416111199 S2P_Cfg1_SW_Ver_Byte3_31 "SBMU软件版本号Byte3对应的ASCII码";
CM_ SG_ 2416111199 S2P_Cfg1_SW_Ver_Byte4_31 "SBMU软件版本号Byte4对应的ASCII码";
CM_ SG_ 2416111199 S2P_Cfg1_SW_Ver_Byte5_31 "SBMU软件版本号Byte5对应的ASCII码";
CM_ SG_ 2416111199 S2P_Cfg1_SW_Ver_Byte6_31 "SBMU软件版本号Byte6对应的ASCII码";
CM_ SG_ 2416111199 S2P_Cfg1_SW_Ver_Byte7_31 "SBMU软件版本号Byte7对应的ASCII码";
CM_ SG_ 2416111199 S2P_Cfg1_SW_Ver_Byte8_31 "SBMU软件版本号Byte8对应的ASCII码";
CM_ SG_ 2416111200 S2P_Cfg1_SW_Ver_Byte1_32 "SBMU软件版本号最低字节Byte1对应的ASCII码";
CM_ SG_ 2416111200 S2P_Cfg1_SW_Ver_Byte2_32 "SBMU软件版本号Byte2对应的ASCII码";
CM_ SG_ 2416111200 S2P_Cfg1_SW_Ver_Byte3_32 "SBMU软件版本号Byte3对应的ASCII码";
CM_ SG_ 2416111200 S2P_Cfg1_SW_Ver_Byte4_32 "SBMU软件版本号Byte4对应的ASCII码";
CM_ SG_ 2416111200 S2P_Cfg1_SW_Ver_Byte5_32 "SBMU软件版本号Byte5对应的ASCII码";
CM_ SG_ 2416111200 S2P_Cfg1_SW_Ver_Byte6_32 "SBMU软件版本号Byte6对应的ASCII码";
CM_ SG_ 2416111200 S2P_Cfg1_SW_Ver_Byte7_32 "SBMU软件版本号Byte7对应的ASCII码";
CM_ SG_ 2416111200 S2P_Cfg1_SW_Ver_Byte8_32 "SBMU软件版本号Byte8对应的ASCII码";
CM_ SG_ 2416111201 S2P_Cfg1_SW_Ver_Byte1_33 "SBMU软件版本号最低字节Byte1对应的ASCII码";
CM_ SG_ 2416111201 S2P_Cfg1_SW_Ver_Byte2_33 "SBMU软件版本号Byte2对应的ASCII码";
CM_ SG_ 2416111201 S2P_Cfg1_SW_Ver_Byte3_33 "SBMU软件版本号Byte3对应的ASCII码";
CM_ SG_ 2416111201 S2P_Cfg1_SW_Ver_Byte4_33 "SBMU软件版本号Byte4对应的ASCII码";
CM_ SG_ 2416111201 S2P_Cfg1_SW_Ver_Byte5_33 "SBMU软件版本号Byte5对应的ASCII码";
CM_ SG_ 2416111201 S2P_Cfg1_SW_Ver_Byte6_33 "SBMU软件版本号Byte6对应的ASCII码";
CM_ SG_ 2416111201 S2P_Cfg1_SW_Ver_Byte7_33 "SBMU软件版本号Byte7对应的ASCII码";
CM_ SG_ 2416111201 S2P_Cfg1_SW_Ver_Byte8_33 "SBMU软件版本号Byte8对应的ASCII码";
CM_ SG_ 2416111202 S2P_Cfg1_SW_Ver_Byte1_34 "SBMU软件版本号最低字节Byte1对应的ASCII码";
CM_ SG_ 2416111202 S2P_Cfg1_SW_Ver_Byte2_34 "SBMU软件版本号Byte2对应的ASCII码";
CM_ SG_ 2416111202 S2P_Cfg1_SW_Ver_Byte3_34 "SBMU软件版本号Byte3对应的ASCII码";
CM_ SG_ 2416111202 S2P_Cfg1_SW_Ver_Byte4_34 "SBMU软件版本号Byte4对应的ASCII码";
CM_ SG_ 2416111202 S2P_Cfg1_SW_Ver_Byte5_34 "SBMU软件版本号Byte5对应的ASCII码";
CM_ SG_ 2416111202 S2P_Cfg1_SW_Ver_Byte6_34 "SBMU软件版本号Byte6对应的ASCII码";
CM_ SG_ 2416111202 S2P_Cfg1_SW_Ver_Byte7_34 "SBMU软件版本号Byte7对应的ASCII码";
CM_ SG_ 2416111202 S2P_Cfg1_SW_Ver_Byte8_34 "SBMU软件版本号Byte8对应的ASCII码";
CM_ SG_ 2416111203 S2P_Cfg1_SW_Ver_Byte1_35 "SBMU软件版本号最低字节Byte1对应的ASCII码";
CM_ SG_ 2416111203 S2P_Cfg1_SW_Ver_Byte2_35 "SBMU软件版本号Byte2对应的ASCII码";
CM_ SG_ 2416111203 S2P_Cfg1_SW_Ver_Byte3_35 "SBMU软件版本号Byte3对应的ASCII码";
CM_ SG_ 2416111203 S2P_Cfg1_SW_Ver_Byte4_35 "SBMU软件版本号Byte4对应的ASCII码";
CM_ SG_ 2416111203 S2P_Cfg1_SW_Ver_Byte5_35 "SBMU软件版本号Byte5对应的ASCII码";
CM_ SG_ 2416111203 S2P_Cfg1_SW_Ver_Byte6_35 "SBMU软件版本号Byte6对应的ASCII码";
CM_ SG_ 2416111203 S2P_Cfg1_SW_Ver_Byte7_35 "SBMU软件版本号Byte7对应的ASCII码";
CM_ SG_ 2416111203 S2P_Cfg1_SW_Ver_Byte8_35 "SBMU软件版本号Byte8对应的ASCII码";
CM_ SG_ 2416111204 S2P_Cfg1_SW_Ver_Byte1_36 "SBMU软件版本号最低字节Byte1对应的ASCII码";
CM_ SG_ 2416111204 S2P_Cfg1_SW_Ver_Byte2_36 "SBMU软件版本号Byte2对应的ASCII码";
CM_ SG_ 2416111204 S2P_Cfg1_SW_Ver_Byte3_36 "SBMU软件版本号Byte3对应的ASCII码";
CM_ SG_ 2416111204 S2P_Cfg1_SW_Ver_Byte4_36 "SBMU软件版本号Byte4对应的ASCII码";
CM_ SG_ 2416111204 S2P_Cfg1_SW_Ver_Byte5_36 "SBMU软件版本号Byte5对应的ASCII码";
CM_ SG_ 2416111204 S2P_Cfg1_SW_Ver_Byte6_36 "SBMU软件版本号Byte6对应的ASCII码";
CM_ SG_ 2416111204 S2P_Cfg1_SW_Ver_Byte7_36 "SBMU软件版本号Byte7对应的ASCII码";
CM_ SG_ 2416111204 S2P_Cfg1_SW_Ver_Byte8_36 "SBMU软件版本号Byte8对应的ASCII码";
CM_ SG_ 2416111205 S2P_Cfg1_SW_Ver_Byte1_37 "SBMU软件版本号最低字节Byte1对应的ASCII码";
CM_ SG_ 2416111205 S2P_Cfg1_SW_Ver_Byte2_37 "SBMU软件版本号Byte2对应的ASCII码";
CM_ SG_ 2416111205 S2P_Cfg1_SW_Ver_Byte3_37 "SBMU软件版本号Byte3对应的ASCII码";
CM_ SG_ 2416111205 S2P_Cfg1_SW_Ver_Byte4_37 "SBMU软件版本号Byte4对应的ASCII码";
CM_ SG_ 2416111205 S2P_Cfg1_SW_Ver_Byte5_37 "SBMU软件版本号Byte5对应的ASCII码";
CM_ SG_ 2416111205 S2P_Cfg1_SW_Ver_Byte6_37 "SBMU软件版本号Byte6对应的ASCII码";
CM_ SG_ 2416111205 S2P_Cfg1_SW_Ver_Byte7_37 "SBMU软件版本号Byte7对应的ASCII码";
CM_ SG_ 2416111205 S2P_Cfg1_SW_Ver_Byte8_37 "SBMU软件版本号Byte8对应的ASCII码";
CM_ SG_ 2416111206 S2P_Cfg1_SW_Ver_Byte1_38 "SBMU软件版本号最低字节Byte1对应的ASCII码";
CM_ SG_ 2416111206 S2P_Cfg1_SW_Ver_Byte2_38 "SBMU软件版本号Byte2对应的ASCII码";
CM_ SG_ 2416111206 S2P_Cfg1_SW_Ver_Byte3_38 "SBMU软件版本号Byte3对应的ASCII码";
CM_ SG_ 2416111206 S2P_Cfg1_SW_Ver_Byte4_38 "SBMU软件版本号Byte4对应的ASCII码";
CM_ SG_ 2416111206 S2P_Cfg1_SW_Ver_Byte5_38 "SBMU软件版本号Byte5对应的ASCII码";
CM_ SG_ 2416111206 S2P_Cfg1_SW_Ver_Byte6_38 "SBMU软件版本号Byte6对应的ASCII码";
CM_ SG_ 2416111206 S2P_Cfg1_SW_Ver_Byte7_38 "SBMU软件版本号Byte7对应的ASCII码";
CM_ SG_ 2416111206 S2P_Cfg1_SW_Ver_Byte8_38 "SBMU软件版本号Byte8对应的ASCII码";
CM_ SG_ 2416111207 S2P_Cfg1_SW_Ver_Byte1_39 "SBMU软件版本号最低字节Byte1对应的ASCII码";
CM_ SG_ 2416111207 S2P_Cfg1_SW_Ver_Byte2_39 "SBMU软件版本号Byte2对应的ASCII码";
CM_ SG_ 2416111207 S2P_Cfg1_SW_Ver_Byte3_39 "SBMU软件版本号Byte3对应的ASCII码";
CM_ SG_ 2416111207 S2P_Cfg1_SW_Ver_Byte4_39 "SBMU软件版本号Byte4对应的ASCII码";
CM_ SG_ 2416111207 S2P_Cfg1_SW_Ver_Byte5_39 "SBMU软件版本号Byte5对应的ASCII码";
CM_ SG_ 2416111207 S2P_Cfg1_SW_Ver_Byte6_39 "SBMU软件版本号Byte6对应的ASCII码";
CM_ SG_ 2416111207 S2P_Cfg1_SW_Ver_Byte7_39 "SBMU软件版本号Byte7对应的ASCII码";
CM_ SG_ 2416111207 S2P_Cfg1_SW_Ver_Byte8_39 "SBMU软件版本号Byte8对应的ASCII码";
CM_ SG_ 2416111208 S2P_Cfg1_SW_Ver_Byte1_40 "SBMU软件版本号最低字节Byte1对应的ASCII码";
CM_ SG_ 2416111208 S2P_Cfg1_SW_Ver_Byte2_40 "SBMU软件版本号Byte2对应的ASCII码";
CM_ SG_ 2416111208 S2P_Cfg1_SW_Ver_Byte3_40 "SBMU软件版本号Byte3对应的ASCII码";
CM_ SG_ 2416111208 S2P_Cfg1_SW_Ver_Byte4_40 "SBMU软件版本号Byte4对应的ASCII码";
CM_ SG_ 2416111208 S2P_Cfg1_SW_Ver_Byte5_40 "SBMU软件版本号Byte5对应的ASCII码";
CM_ SG_ 2416111208 S2P_Cfg1_SW_Ver_Byte6_40 "SBMU软件版本号Byte6对应的ASCII码";
CM_ SG_ 2416111208 S2P_Cfg1_SW_Ver_Byte7_40 "SBMU软件版本号Byte7对应的ASCII码";
CM_ SG_ 2416111208 S2P_Cfg1_SW_Ver_Byte8_40 "SBMU软件版本号Byte8对应的ASCII码";
CM_ SG_ 2416111209 S2P_Cfg1_SW_Ver_Byte1_41 "SBMU软件版本号最低字节Byte1对应的ASCII码";
CM_ SG_ 2416111209 S2P_Cfg1_SW_Ver_Byte2_41 "SBMU软件版本号Byte2对应的ASCII码";
CM_ SG_ 2416111209 S2P_Cfg1_SW_Ver_Byte3_41 "SBMU软件版本号Byte3对应的ASCII码";
CM_ SG_ 2416111209 S2P_Cfg1_SW_Ver_Byte4_41 "SBMU软件版本号Byte4对应的ASCII码";
CM_ SG_ 2416111209 S2P_Cfg1_SW_Ver_Byte5_41 "SBMU软件版本号Byte5对应的ASCII码";
CM_ SG_ 2416111209 S2P_Cfg1_SW_Ver_Byte6_41 "SBMU软件版本号Byte6对应的ASCII码";
CM_ SG_ 2416111209 S2P_Cfg1_SW_Ver_Byte7_41 "SBMU软件版本号Byte7对应的ASCII码";
CM_ SG_ 2416111209 S2P_Cfg1_SW_Ver_Byte8_41 "SBMU软件版本号Byte8对应的ASCII码";
CM_ SG_ 2416111210 S2P_Cfg1_SW_Ver_Byte1_42 "SBMU软件版本号最低字节Byte1对应的ASCII码";
CM_ SG_ 2416111210 S2P_Cfg1_SW_Ver_Byte2_42 "SBMU软件版本号Byte2对应的ASCII码";
CM_ SG_ 2416111210 S2P_Cfg1_SW_Ver_Byte3_42 "SBMU软件版本号Byte3对应的ASCII码";
CM_ SG_ 2416111210 S2P_Cfg1_SW_Ver_Byte4_42 "SBMU软件版本号Byte4对应的ASCII码";
CM_ SG_ 2416111210 S2P_Cfg1_SW_Ver_Byte5_42 "SBMU软件版本号Byte5对应的ASCII码";
CM_ SG_ 2416111210 S2P_Cfg1_SW_Ver_Byte6_42 "SBMU软件版本号Byte6对应的ASCII码";
CM_ SG_ 2416111210 S2P_Cfg1_SW_Ver_Byte7_42 "SBMU软件版本号Byte7对应的ASCII码";
CM_ SG_ 2416111210 S2P_Cfg1_SW_Ver_Byte8_42 "SBMU软件版本号Byte8对应的ASCII码";
CM_ SG_ 2416111211 S2P_Cfg1_SW_Ver_Byte1_43 "SBMU软件版本号最低字节Byte1对应的ASCII码";
CM_ SG_ 2416111211 S2P_Cfg1_SW_Ver_Byte2_43 "SBMU软件版本号Byte2对应的ASCII码";
CM_ SG_ 2416111211 S2P_Cfg1_SW_Ver_Byte3_43 "SBMU软件版本号Byte3对应的ASCII码";
CM_ SG_ 2416111211 S2P_Cfg1_SW_Ver_Byte4_43 "SBMU软件版本号Byte4对应的ASCII码";
CM_ SG_ 2416111211 S2P_Cfg1_SW_Ver_Byte5_43 "SBMU软件版本号Byte5对应的ASCII码";
CM_ SG_ 2416111211 S2P_Cfg1_SW_Ver_Byte6_43 "SBMU软件版本号Byte6对应的ASCII码";
CM_ SG_ 2416111211 S2P_Cfg1_SW_Ver_Byte7_43 "SBMU软件版本号Byte7对应的ASCII码";
CM_ SG_ 2416111211 S2P_Cfg1_SW_Ver_Byte8_43 "SBMU软件版本号Byte8对应的ASCII码";
CM_ SG_ 2416111212 S2P_Cfg1_SW_Ver_Byte1_44 "SBMU软件版本号最低字节Byte1对应的ASCII码";
CM_ SG_ 2416111212 S2P_Cfg1_SW_Ver_Byte2_44 "SBMU软件版本号Byte2对应的ASCII码";
CM_ SG_ 2416111212 S2P_Cfg1_SW_Ver_Byte3_44 "SBMU软件版本号Byte3对应的ASCII码";
CM_ SG_ 2416111212 S2P_Cfg1_SW_Ver_Byte4_44 "SBMU软件版本号Byte4对应的ASCII码";
CM_ SG_ 2416111212 S2P_Cfg1_SW_Ver_Byte5_44 "SBMU软件版本号Byte5对应的ASCII码";
CM_ SG_ 2416111212 S2P_Cfg1_SW_Ver_Byte6_44 "SBMU软件版本号Byte6对应的ASCII码";
CM_ SG_ 2416111212 S2P_Cfg1_SW_Ver_Byte7_44 "SBMU软件版本号Byte7对应的ASCII码";
CM_ SG_ 2416111212 S2P_Cfg1_SW_Ver_Byte8_44 "SBMU软件版本号Byte8对应的ASCII码";
CM_ SG_ 2416111213 S2P_Cfg1_SW_Ver_Byte1_45 "SBMU软件版本号最低字节Byte1对应的ASCII码";
CM_ SG_ 2416111213 S2P_Cfg1_SW_Ver_Byte2_45 "SBMU软件版本号Byte2对应的ASCII码";
CM_ SG_ 2416111213 S2P_Cfg1_SW_Ver_Byte3_45 "SBMU软件版本号Byte3对应的ASCII码";
CM_ SG_ 2416111213 S2P_Cfg1_SW_Ver_Byte4_45 "SBMU软件版本号Byte4对应的ASCII码";
CM_ SG_ 2416111213 S2P_Cfg1_SW_Ver_Byte5_45 "SBMU软件版本号Byte5对应的ASCII码";
CM_ SG_ 2416111213 S2P_Cfg1_SW_Ver_Byte6_45 "SBMU软件版本号Byte6对应的ASCII码";
CM_ SG_ 2416111213 S2P_Cfg1_SW_Ver_Byte7_45 "SBMU软件版本号Byte7对应的ASCII码";
CM_ SG_ 2416111213 S2P_Cfg1_SW_Ver_Byte8_45 "SBMU软件版本号Byte8对应的ASCII码";
CM_ SG_ 2416111214 S2P_Cfg1_SW_Ver_Byte1_46 "SBMU软件版本号最低字节Byte1对应的ASCII码";
CM_ SG_ 2416111214 S2P_Cfg1_SW_Ver_Byte2_46 "SBMU软件版本号Byte2对应的ASCII码";
CM_ SG_ 2416111214 S2P_Cfg1_SW_Ver_Byte3_46 "SBMU软件版本号Byte3对应的ASCII码";
CM_ SG_ 2416111214 S2P_Cfg1_SW_Ver_Byte4_46 "SBMU软件版本号Byte4对应的ASCII码";
CM_ SG_ 2416111214 S2P_Cfg1_SW_Ver_Byte5_46 "SBMU软件版本号Byte5对应的ASCII码";
CM_ SG_ 2416111214 S2P_Cfg1_SW_Ver_Byte6_46 "SBMU软件版本号Byte6对应的ASCII码";
CM_ SG_ 2416111214 S2P_Cfg1_SW_Ver_Byte7_46 "SBMU软件版本号Byte7对应的ASCII码";
CM_ SG_ 2416111214 S2P_Cfg1_SW_Ver_Byte8_46 "SBMU软件版本号Byte8对应的ASCII码";
CM_ SG_ 2416111215 S2P_Cfg1_SW_Ver_Byte1_47 "SBMU软件版本号最低字节Byte1对应的ASCII码";
CM_ SG_ 2416111215 S2P_Cfg1_SW_Ver_Byte2_47 "SBMU软件版本号Byte2对应的ASCII码";
CM_ SG_ 2416111215 S2P_Cfg1_SW_Ver_Byte3_47 "SBMU软件版本号Byte3对应的ASCII码";
CM_ SG_ 2416111215 S2P_Cfg1_SW_Ver_Byte4_47 "SBMU软件版本号Byte4对应的ASCII码";
CM_ SG_ 2416111215 S2P_Cfg1_SW_Ver_Byte5_47 "SBMU软件版本号Byte5对应的ASCII码";
CM_ SG_ 2416111215 S2P_Cfg1_SW_Ver_Byte6_47 "SBMU软件版本号Byte6对应的ASCII码";
CM_ SG_ 2416111215 S2P_Cfg1_SW_Ver_Byte7_47 "SBMU软件版本号Byte7对应的ASCII码";
CM_ SG_ 2416111215 S2P_Cfg1_SW_Ver_Byte8_47 "SBMU软件版本号Byte8对应的ASCII码";
CM_ SG_ 2416111216 S2P_Cfg1_SW_Ver_Byte1_48 "SBMU软件版本号最低字节Byte1对应的ASCII码";
CM_ SG_ 2416111216 S2P_Cfg1_SW_Ver_Byte2_48 "SBMU软件版本号Byte2对应的ASCII码";
CM_ SG_ 2416111216 S2P_Cfg1_SW_Ver_Byte3_48 "SBMU软件版本号Byte3对应的ASCII码";
CM_ SG_ 2416111216 S2P_Cfg1_SW_Ver_Byte4_48 "SBMU软件版本号Byte4对应的ASCII码";
CM_ SG_ 2416111216 S2P_Cfg1_SW_Ver_Byte5_48 "SBMU软件版本号Byte5对应的ASCII码";
CM_ SG_ 2416111216 S2P_Cfg1_SW_Ver_Byte6_48 "SBMU软件版本号Byte6对应的ASCII码";
CM_ SG_ 2416111216 S2P_Cfg1_SW_Ver_Byte7_48 "SBMU软件版本号Byte7对应的ASCII码";
CM_ SG_ 2416111216 S2P_Cfg1_SW_Ver_Byte8_48 "SBMU软件版本号Byte8对应的ASCII码";
CM_ SG_ 2416111217 S2P_Cfg1_SW_Ver_Byte1_49 "SBMU软件版本号最低字节Byte1对应的ASCII码";
CM_ SG_ 2416111217 S2P_Cfg1_SW_Ver_Byte2_49 "SBMU软件版本号Byte2对应的ASCII码";
CM_ SG_ 2416111217 S2P_Cfg1_SW_Ver_Byte3_49 "SBMU软件版本号Byte3对应的ASCII码";
CM_ SG_ 2416111217 S2P_Cfg1_SW_Ver_Byte4_49 "SBMU软件版本号Byte4对应的ASCII码";
CM_ SG_ 2416111217 S2P_Cfg1_SW_Ver_Byte5_49 "SBMU软件版本号Byte5对应的ASCII码";
CM_ SG_ 2416111217 S2P_Cfg1_SW_Ver_Byte6_49 "SBMU软件版本号Byte6对应的ASCII码";
CM_ SG_ 2416111217 S2P_Cfg1_SW_Ver_Byte7_49 "SBMU软件版本号Byte7对应的ASCII码";
CM_ SG_ 2416111217 S2P_Cfg1_SW_Ver_Byte8_49 "SBMU软件版本号Byte8对应的ASCII码";
CM_ SG_ 2416111218 S2P_Cfg1_SW_Ver_Byte1_50 "SBMU软件版本号最低字节Byte1对应的ASCII码";
CM_ SG_ 2416111218 S2P_Cfg1_SW_Ver_Byte2_50 "SBMU软件版本号Byte2对应的ASCII码";
CM_ SG_ 2416111218 S2P_Cfg1_SW_Ver_Byte3_50 "SBMU软件版本号Byte3对应的ASCII码";
CM_ SG_ 2416111218 S2P_Cfg1_SW_Ver_Byte4_50 "SBMU软件版本号Byte4对应的ASCII码";
CM_ SG_ 2416111218 S2P_Cfg1_SW_Ver_Byte5_50 "SBMU软件版本号Byte5对应的ASCII码";
CM_ SG_ 2416111218 S2P_Cfg1_SW_Ver_Byte6_50 "SBMU软件版本号Byte6对应的ASCII码";
CM_ SG_ 2416111218 S2P_Cfg1_SW_Ver_Byte7_50 "SBMU软件版本号Byte7对应的ASCII码";
CM_ SG_ 2416111218 S2P_Cfg1_SW_Ver_Byte8_50 "SBMU软件版本号Byte8对应的ASCII码";
CM_ SG_ 2416111219 S2P_Cfg1_SW_Ver_Byte1_51 "SBMU软件版本号最低字节Byte1对应的ASCII码";
CM_ SG_ 2416111219 S2P_Cfg1_SW_Ver_Byte2_51 "SBMU软件版本号Byte2对应的ASCII码";
CM_ SG_ 2416111219 S2P_Cfg1_SW_Ver_Byte3_51 "SBMU软件版本号Byte3对应的ASCII码";
CM_ SG_ 2416111219 S2P_Cfg1_SW_Ver_Byte4_51 "SBMU软件版本号Byte4对应的ASCII码";
CM_ SG_ 2416111219 S2P_Cfg1_SW_Ver_Byte5_51 "SBMU软件版本号Byte5对应的ASCII码";
CM_ SG_ 2416111219 S2P_Cfg1_SW_Ver_Byte6_51 "SBMU软件版本号Byte6对应的ASCII码";
CM_ SG_ 2416111219 S2P_Cfg1_SW_Ver_Byte7_51 "SBMU软件版本号Byte7对应的ASCII码";
CM_ SG_ 2416111219 S2P_Cfg1_SW_Ver_Byte8_51 "SBMU软件版本号Byte8对应的ASCII码";
CM_ SG_ 2416111220 S2P_Cfg1_SW_Ver_Byte1_52 "SBMU软件版本号最低字节Byte1对应的ASCII码";
CM_ SG_ 2416111220 S2P_Cfg1_SW_Ver_Byte2_52 "SBMU软件版本号Byte2对应的ASCII码";
CM_ SG_ 2416111220 S2P_Cfg1_SW_Ver_Byte3_52 "SBMU软件版本号Byte3对应的ASCII码";
CM_ SG_ 2416111220 S2P_Cfg1_SW_Ver_Byte4_52 "SBMU软件版本号Byte4对应的ASCII码";
CM_ SG_ 2416111220 S2P_Cfg1_SW_Ver_Byte5_52 "SBMU软件版本号Byte5对应的ASCII码";
CM_ SG_ 2416111220 S2P_Cfg1_SW_Ver_Byte6_52 "SBMU软件版本号Byte6对应的ASCII码";
CM_ SG_ 2416111220 S2P_Cfg1_SW_Ver_Byte7_52 "SBMU软件版本号Byte7对应的ASCII码";
CM_ SG_ 2416111220 S2P_Cfg1_SW_Ver_Byte8_52 "SBMU软件版本号Byte8对应的ASCII码";
CM_ SG_ 2416111221 S2P_Cfg1_SW_Ver_Byte1_53 "SBMU软件版本号最低字节Byte1对应的ASCII码";
CM_ SG_ 2416111221 S2P_Cfg1_SW_Ver_Byte2_53 "SBMU软件版本号Byte2对应的ASCII码";
CM_ SG_ 2416111221 S2P_Cfg1_SW_Ver_Byte3_53 "SBMU软件版本号Byte3对应的ASCII码";
CM_ SG_ 2416111221 S2P_Cfg1_SW_Ver_Byte4_53 "SBMU软件版本号Byte4对应的ASCII码";
CM_ SG_ 2416111221 S2P_Cfg1_SW_Ver_Byte5_53 "SBMU软件版本号Byte5对应的ASCII码";
CM_ SG_ 2416111221 S2P_Cfg1_SW_Ver_Byte6_53 "SBMU软件版本号Byte6对应的ASCII码";
CM_ SG_ 2416111221 S2P_Cfg1_SW_Ver_Byte7_53 "SBMU软件版本号Byte7对应的ASCII码";
CM_ SG_ 2416111221 S2P_Cfg1_SW_Ver_Byte8_53 "SBMU软件版本号Byte8对应的ASCII码";
CM_ SG_ 2416111222 S2P_Cfg1_SW_Ver_Byte1_54 "SBMU软件版本号最低字节Byte1对应的ASCII码";
CM_ SG_ 2416111222 S2P_Cfg1_SW_Ver_Byte2_54 "SBMU软件版本号Byte2对应的ASCII码";
CM_ SG_ 2416111222 S2P_Cfg1_SW_Ver_Byte3_54 "SBMU软件版本号Byte3对应的ASCII码";
CM_ SG_ 2416111222 S2P_Cfg1_SW_Ver_Byte4_54 "SBMU软件版本号Byte4对应的ASCII码";
CM_ SG_ 2416111222 S2P_Cfg1_SW_Ver_Byte5_54 "SBMU软件版本号Byte5对应的ASCII码";
CM_ SG_ 2416111222 S2P_Cfg1_SW_Ver_Byte6_54 "SBMU软件版本号Byte6对应的ASCII码";
CM_ SG_ 2416111222 S2P_Cfg1_SW_Ver_Byte7_54 "SBMU软件版本号Byte7对应的ASCII码";
CM_ SG_ 2416111222 S2P_Cfg1_SW_Ver_Byte8_54 "SBMU软件版本号Byte8对应的ASCII码";
CM_ SG_ 2416111223 S2P_Cfg1_SW_Ver_Byte1_55 "SBMU软件版本号最低字节Byte1对应的ASCII码";
CM_ SG_ 2416111223 S2P_Cfg1_SW_Ver_Byte2_55 "SBMU软件版本号Byte2对应的ASCII码";
CM_ SG_ 2416111223 S2P_Cfg1_SW_Ver_Byte3_55 "SBMU软件版本号Byte3对应的ASCII码";
CM_ SG_ 2416111223 S2P_Cfg1_SW_Ver_Byte4_55 "SBMU软件版本号Byte4对应的ASCII码";
CM_ SG_ 2416111223 S2P_Cfg1_SW_Ver_Byte5_55 "SBMU软件版本号Byte5对应的ASCII码";
CM_ SG_ 2416111223 S2P_Cfg1_SW_Ver_Byte6_55 "SBMU软件版本号Byte6对应的ASCII码";
CM_ SG_ 2416111223 S2P_Cfg1_SW_Ver_Byte7_55 "SBMU软件版本号Byte7对应的ASCII码";
CM_ SG_ 2416111223 S2P_Cfg1_SW_Ver_Byte8_55 "SBMU软件版本号Byte8对应的ASCII码";
CM_ SG_ 2416111224 S2P_Cfg1_SW_Ver_Byte1_56 "SBMU软件版本号最低字节Byte1对应的ASCII码";
CM_ SG_ 2416111224 S2P_Cfg1_SW_Ver_Byte2_56 "SBMU软件版本号Byte2对应的ASCII码";
CM_ SG_ 2416111224 S2P_Cfg1_SW_Ver_Byte3_56 "SBMU软件版本号Byte3对应的ASCII码";
CM_ SG_ 2416111224 S2P_Cfg1_SW_Ver_Byte4_56 "SBMU软件版本号Byte4对应的ASCII码";
CM_ SG_ 2416111224 S2P_Cfg1_SW_Ver_Byte5_56 "SBMU软件版本号Byte5对应的ASCII码";
CM_ SG_ 2416111224 S2P_Cfg1_SW_Ver_Byte6_56 "SBMU软件版本号Byte6对应的ASCII码";
CM_ SG_ 2416111224 S2P_Cfg1_SW_Ver_Byte7_56 "SBMU软件版本号Byte7对应的ASCII码";
CM_ SG_ 2416111224 S2P_Cfg1_SW_Ver_Byte8_56 "SBMU软件版本号Byte8对应的ASCII码";
CM_ SG_ 2416111225 S2P_Cfg1_SW_Ver_Byte1_57 "SBMU软件版本号最低字节Byte1对应的ASCII码";
CM_ SG_ 2416111225 S2P_Cfg1_SW_Ver_Byte2_57 "SBMU软件版本号Byte2对应的ASCII码";
CM_ SG_ 2416111225 S2P_Cfg1_SW_Ver_Byte3_57 "SBMU软件版本号Byte3对应的ASCII码";
CM_ SG_ 2416111225 S2P_Cfg1_SW_Ver_Byte4_57 "SBMU软件版本号Byte4对应的ASCII码";
CM_ SG_ 2416111225 S2P_Cfg1_SW_Ver_Byte5_57 "SBMU软件版本号Byte5对应的ASCII码";
CM_ SG_ 2416111225 S2P_Cfg1_SW_Ver_Byte6_57 "SBMU软件版本号Byte6对应的ASCII码";
CM_ SG_ 2416111225 S2P_Cfg1_SW_Ver_Byte7_57 "SBMU软件版本号Byte7对应的ASCII码";
CM_ SG_ 2416111225 S2P_Cfg1_SW_Ver_Byte8_57 "SBMU软件版本号Byte8对应的ASCII码";
CM_ SG_ 2416111226 S2P_Cfg1_SW_Ver_Byte1_58 "SBMU软件版本号最低字节Byte1对应的ASCII码";
CM_ SG_ 2416111226 S2P_Cfg1_SW_Ver_Byte2_58 "SBMU软件版本号Byte2对应的ASCII码";
CM_ SG_ 2416111226 S2P_Cfg1_SW_Ver_Byte3_58 "SBMU软件版本号Byte3对应的ASCII码";
CM_ SG_ 2416111226 S2P_Cfg1_SW_Ver_Byte4_58 "SBMU软件版本号Byte4对应的ASCII码";
CM_ SG_ 2416111226 S2P_Cfg1_SW_Ver_Byte5_58 "SBMU软件版本号Byte5对应的ASCII码";
CM_ SG_ 2416111226 S2P_Cfg1_SW_Ver_Byte6_58 "SBMU软件版本号Byte6对应的ASCII码";
CM_ SG_ 2416111226 S2P_Cfg1_SW_Ver_Byte7_58 "SBMU软件版本号Byte7对应的ASCII码";
CM_ SG_ 2416111226 S2P_Cfg1_SW_Ver_Byte8_58 "SBMU软件版本号Byte8对应的ASCII码";
CM_ SG_ 2416111227 S2P_Cfg1_SW_Ver_Byte1_59 "SBMU软件版本号最低字节Byte1对应的ASCII码";
CM_ SG_ 2416111227 S2P_Cfg1_SW_Ver_Byte2_59 "SBMU软件版本号Byte2对应的ASCII码";
CM_ SG_ 2416111227 S2P_Cfg1_SW_Ver_Byte3_59 "SBMU软件版本号Byte3对应的ASCII码";
CM_ SG_ 2416111227 S2P_Cfg1_SW_Ver_Byte4_59 "SBMU软件版本号Byte4对应的ASCII码";
CM_ SG_ 2416111227 S2P_Cfg1_SW_Ver_Byte5_59 "SBMU软件版本号Byte5对应的ASCII码";
CM_ SG_ 2416111227 S2P_Cfg1_SW_Ver_Byte6_59 "SBMU软件版本号Byte6对应的ASCII码";
CM_ SG_ 2416111227 S2P_Cfg1_SW_Ver_Byte7_59 "SBMU软件版本号Byte7对应的ASCII码";
CM_ SG_ 2416111227 S2P_Cfg1_SW_Ver_Byte8_59 "SBMU软件版本号Byte8对应的ASCII码";
CM_ SG_ 2416111228 S2P_Cfg1_SW_Ver_Byte1_60 "SBMU软件版本号最低字节Byte1对应的ASCII码";
CM_ SG_ 2416111228 S2P_Cfg1_SW_Ver_Byte2_60 "SBMU软件版本号Byte2对应的ASCII码";
CM_ SG_ 2416111228 S2P_Cfg1_SW_Ver_Byte3_60 "SBMU软件版本号Byte3对应的ASCII码";
CM_ SG_ 2416111228 S2P_Cfg1_SW_Ver_Byte4_60 "SBMU软件版本号Byte4对应的ASCII码";
CM_ SG_ 2416111228 S2P_Cfg1_SW_Ver_Byte5_60 "SBMU软件版本号Byte5对应的ASCII码";
CM_ SG_ 2416111228 S2P_Cfg1_SW_Ver_Byte6_60 "SBMU软件版本号Byte6对应的ASCII码";
CM_ SG_ 2416111228 S2P_Cfg1_SW_Ver_Byte7_60 "SBMU软件版本号Byte7对应的ASCII码";
CM_ SG_ 2416111228 S2P_Cfg1_SW_Ver_Byte8_60 "SBMU软件版本号Byte8对应的ASCII码";
CM_ SG_ 2416111229 S2P_Cfg1_SW_Ver_Byte1_61 "SBMU软件版本号最低字节Byte1对应的ASCII码";
CM_ SG_ 2416111229 S2P_Cfg1_SW_Ver_Byte2_61 "SBMU软件版本号Byte2对应的ASCII码";
CM_ SG_ 2416111229 S2P_Cfg1_SW_Ver_Byte3_61 "SBMU软件版本号Byte3对应的ASCII码";
CM_ SG_ 2416111229 S2P_Cfg1_SW_Ver_Byte4_61 "SBMU软件版本号Byte4对应的ASCII码";
CM_ SG_ 2416111229 S2P_Cfg1_SW_Ver_Byte5_61 "SBMU软件版本号Byte5对应的ASCII码";
CM_ SG_ 2416111229 S2P_Cfg1_SW_Ver_Byte6_61 "SBMU软件版本号Byte6对应的ASCII码";
CM_ SG_ 2416111229 S2P_Cfg1_SW_Ver_Byte7_61 "SBMU软件版本号Byte7对应的ASCII码";
CM_ SG_ 2416111229 S2P_Cfg1_SW_Ver_Byte8_61 "SBMU软件版本号Byte8对应的ASCII码";
CM_ SG_ 2416111230 S2P_Cfg1_SW_Ver_Byte1_62 "SBMU软件版本号最低字节Byte1对应的ASCII码";
CM_ SG_ 2416111230 S2P_Cfg1_SW_Ver_Byte2_62 "SBMU软件版本号Byte2对应的ASCII码";
CM_ SG_ 2416111230 S2P_Cfg1_SW_Ver_Byte3_62 "SBMU软件版本号Byte3对应的ASCII码";
CM_ SG_ 2416111230 S2P_Cfg1_SW_Ver_Byte4_62 "SBMU软件版本号Byte4对应的ASCII码";
CM_ SG_ 2416111230 S2P_Cfg1_SW_Ver_Byte5_62 "SBMU软件版本号Byte5对应的ASCII码";
CM_ SG_ 2416111230 S2P_Cfg1_SW_Ver_Byte6_62 "SBMU软件版本号Byte6对应的ASCII码";
CM_ SG_ 2416111230 S2P_Cfg1_SW_Ver_Byte7_62 "SBMU软件版本号Byte7对应的ASCII码";
CM_ SG_ 2416111230 S2P_Cfg1_SW_Ver_Byte8_62 "SBMU软件版本号Byte8对应的ASCII码";
CM_ SG_ 2416111231 S2P_Cfg1_SW_Ver_Byte1_63 "SBMU软件版本号最低字节Byte1对应的ASCII码";
CM_ SG_ 2416111231 S2P_Cfg1_SW_Ver_Byte2_63 "SBMU软件版本号Byte2对应的ASCII码";
CM_ SG_ 2416111231 S2P_Cfg1_SW_Ver_Byte3_63 "SBMU软件版本号Byte3对应的ASCII码";
CM_ SG_ 2416111231 S2P_Cfg1_SW_Ver_Byte4_63 "SBMU软件版本号Byte4对应的ASCII码";
CM_ SG_ 2416111231 S2P_Cfg1_SW_Ver_Byte5_63 "SBMU软件版本号Byte5对应的ASCII码";
CM_ SG_ 2416111231 S2P_Cfg1_SW_Ver_Byte6_63 "SBMU软件版本号Byte6对应的ASCII码";
CM_ SG_ 2416111231 S2P_Cfg1_SW_Ver_Byte7_63 "SBMU软件版本号Byte7对应的ASCII码";
CM_ SG_ 2416111231 S2P_Cfg1_SW_Ver_Byte8_63 "SBMU软件版本号Byte8对应的ASCII码";
CM_ SG_ 2416176705 S2P_Cfg2_SW_Ver_Byte9_01 "SBMU软件版本号Byte9对应的ASCII码";
CM_ SG_ 2416176705 S2P_Cfg2_SW_Ver_Byte10_01 "SBMU软件版本号Byte10对应的ASCII码";
CM_ SG_ 2416176705 S2P_Cfg2_SW_Ver_Byte11_01 "SBMU软件版本号Byte11对应的ASCII码";
CM_ SG_ 2416176705 S2P_Cfg2_SW_Ver_Byte12_01 "SBMU软件版本号Byte12对应的ASCII码";
CM_ SG_ 2416176705 S2P_Cfg2_SW_Ver_Byte13_01 "SBMU软件版本号Byte13对应的ASCII码";
CM_ SG_ 2416176705 S2P_Cfg2_SW_Ver_Byte14_01 "SBMU软件版本号Byte14对应的ASCII码";
CM_ SG_ 2416176705 S2P_Cfg2_SW_Ver_Byte15_01 "SBMU软件版本号Byte15对应的ASCII码";
CM_ SG_ 2416176705 S2P_Cfg2_SW_Ver_Byte16_01 "SBMU软件版本号最高字节Byte16对应的ASCII码";
CM_ SG_ 2416176706 S2P_Cfg2_SW_Ver_Byte9_02 "SBMU软件版本号Byte9对应的ASCII码";
CM_ SG_ 2416176706 S2P_Cfg2_SW_Ver_Byte10_02 "SBMU软件版本号Byte10对应的ASCII码";
CM_ SG_ 2416176706 S2P_Cfg2_SW_Ver_Byte11_02 "SBMU软件版本号Byte11对应的ASCII码";
CM_ SG_ 2416176706 S2P_Cfg2_SW_Ver_Byte12_02 "SBMU软件版本号Byte12对应的ASCII码";
CM_ SG_ 2416176706 S2P_Cfg2_SW_Ver_Byte13_02 "SBMU软件版本号Byte13对应的ASCII码";
CM_ SG_ 2416176706 S2P_Cfg2_SW_Ver_Byte14_02 "SBMU软件版本号Byte14对应的ASCII码";
CM_ SG_ 2416176706 S2P_Cfg2_SW_Ver_Byte15_02 "SBMU软件版本号Byte15对应的ASCII码";
CM_ SG_ 2416176706 S2P_Cfg2_SW_Ver_Byte16_02 "SBMU软件版本号最高字节Byte16对应的ASCII码";
CM_ SG_ 2416176707 S2P_Cfg2_SW_Ver_Byte9_03 "SBMU软件版本号Byte9对应的ASCII码";
CM_ SG_ 2416176707 S2P_Cfg2_SW_Ver_Byte10_03 "SBMU软件版本号Byte10对应的ASCII码";
CM_ SG_ 2416176707 S2P_Cfg2_SW_Ver_Byte11_03 "SBMU软件版本号Byte11对应的ASCII码";
CM_ SG_ 2416176707 S2P_Cfg2_SW_Ver_Byte12_03 "SBMU软件版本号Byte12对应的ASCII码";
CM_ SG_ 2416176707 S2P_Cfg2_SW_Ver_Byte13_03 "SBMU软件版本号Byte13对应的ASCII码";
CM_ SG_ 2416176707 S2P_Cfg2_SW_Ver_Byte14_03 "SBMU软件版本号Byte14对应的ASCII码";
CM_ SG_ 2416176707 S2P_Cfg2_SW_Ver_Byte15_03 "SBMU软件版本号Byte15对应的ASCII码";
CM_ SG_ 2416176707 S2P_Cfg2_SW_Ver_Byte16_03 "SBMU软件版本号最高字节Byte16对应的ASCII码";
CM_ SG_ 2416176708 S2P_Cfg2_SW_Ver_Byte9_04 "SBMU软件版本号Byte9对应的ASCII码";
CM_ SG_ 2416176708 S2P_Cfg2_SW_Ver_Byte10_04 "SBMU软件版本号Byte10对应的ASCII码";
CM_ SG_ 2416176708 S2P_Cfg2_SW_Ver_Byte11_04 "SBMU软件版本号Byte11对应的ASCII码";
CM_ SG_ 2416176708 S2P_Cfg2_SW_Ver_Byte12_04 "SBMU软件版本号Byte12对应的ASCII码";
CM_ SG_ 2416176708 S2P_Cfg2_SW_Ver_Byte13_04 "SBMU软件版本号Byte13对应的ASCII码";
CM_ SG_ 2416176708 S2P_Cfg2_SW_Ver_Byte14_04 "SBMU软件版本号Byte14对应的ASCII码";
CM_ SG_ 2416176708 S2P_Cfg2_SW_Ver_Byte15_04 "SBMU软件版本号Byte15对应的ASCII码";
CM_ SG_ 2416176708 S2P_Cfg2_SW_Ver_Byte16_04 "SBMU软件版本号最高字节Byte16对应的ASCII码";
CM_ SG_ 2416176709 S2P_Cfg2_SW_Ver_Byte9_05 "SBMU软件版本号Byte9对应的ASCII码";
CM_ SG_ 2416176709 S2P_Cfg2_SW_Ver_Byte10_05 "SBMU软件版本号Byte10对应的ASCII码";
CM_ SG_ 2416176709 S2P_Cfg2_SW_Ver_Byte11_05 "SBMU软件版本号Byte11对应的ASCII码";
CM_ SG_ 2416176709 S2P_Cfg2_SW_Ver_Byte12_05 "SBMU软件版本号Byte12对应的ASCII码";
CM_ SG_ 2416176709 S2P_Cfg2_SW_Ver_Byte13_05 "SBMU软件版本号Byte13对应的ASCII码";
CM_ SG_ 2416176709 S2P_Cfg2_SW_Ver_Byte14_05 "SBMU软件版本号Byte14对应的ASCII码";
CM_ SG_ 2416176709 S2P_Cfg2_SW_Ver_Byte15_05 "SBMU软件版本号Byte15对应的ASCII码";
CM_ SG_ 2416176709 S2P_Cfg2_SW_Ver_Byte16_05 "SBMU软件版本号最高字节Byte16对应的ASCII码";
CM_ SG_ 2416176710 S2P_Cfg2_SW_Ver_Byte9_06 "SBMU软件版本号Byte9对应的ASCII码";
CM_ SG_ 2416176710 S2P_Cfg2_SW_Ver_Byte10_06 "SBMU软件版本号Byte10对应的ASCII码";
CM_ SG_ 2416176710 S2P_Cfg2_SW_Ver_Byte11_06 "SBMU软件版本号Byte11对应的ASCII码";
CM_ SG_ 2416176710 S2P_Cfg2_SW_Ver_Byte12_06 "SBMU软件版本号Byte12对应的ASCII码";
CM_ SG_ 2416176710 S2P_Cfg2_SW_Ver_Byte13_06 "SBMU软件版本号Byte13对应的ASCII码";
CM_ SG_ 2416176710 S2P_Cfg2_SW_Ver_Byte14_06 "SBMU软件版本号Byte14对应的ASCII码";
CM_ SG_ 2416176710 S2P_Cfg2_SW_Ver_Byte15_06 "SBMU软件版本号Byte15对应的ASCII码";
CM_ SG_ 2416176710 S2P_Cfg2_SW_Ver_Byte16_06 "SBMU软件版本号最高字节Byte16对应的ASCII码";
CM_ SG_ 2416176711 S2P_Cfg2_SW_Ver_Byte9_07 "SBMU软件版本号Byte9对应的ASCII码";
CM_ SG_ 2416176711 S2P_Cfg2_SW_Ver_Byte10_07 "SBMU软件版本号Byte10对应的ASCII码";
CM_ SG_ 2416176711 S2P_Cfg2_SW_Ver_Byte11_07 "SBMU软件版本号Byte11对应的ASCII码";
CM_ SG_ 2416176711 S2P_Cfg2_SW_Ver_Byte12_07 "SBMU软件版本号Byte12对应的ASCII码";
CM_ SG_ 2416176711 S2P_Cfg2_SW_Ver_Byte13_07 "SBMU软件版本号Byte13对应的ASCII码";
CM_ SG_ 2416176711 S2P_Cfg2_SW_Ver_Byte14_07 "SBMU软件版本号Byte14对应的ASCII码";
CM_ SG_ 2416176711 S2P_Cfg2_SW_Ver_Byte15_07 "SBMU软件版本号Byte15对应的ASCII码";
CM_ SG_ 2416176711 S2P_Cfg2_SW_Ver_Byte16_07 "SBMU软件版本号最高字节Byte16对应的ASCII码";
CM_ SG_ 2416176712 S2P_Cfg2_SW_Ver_Byte9_08 "SBMU软件版本号Byte9对应的ASCII码";
CM_ SG_ 2416176712 S2P_Cfg2_SW_Ver_Byte10_08 "SBMU软件版本号Byte10对应的ASCII码";
CM_ SG_ 2416176712 S2P_Cfg2_SW_Ver_Byte11_08 "SBMU软件版本号Byte11对应的ASCII码";
CM_ SG_ 2416176712 S2P_Cfg2_SW_Ver_Byte12_08 "SBMU软件版本号Byte12对应的ASCII码";
CM_ SG_ 2416176712 S2P_Cfg2_SW_Ver_Byte13_08 "SBMU软件版本号Byte13对应的ASCII码";
CM_ SG_ 2416176712 S2P_Cfg2_SW_Ver_Byte14_08 "SBMU软件版本号Byte14对应的ASCII码";
CM_ SG_ 2416176712 S2P_Cfg2_SW_Ver_Byte15_08 "SBMU软件版本号Byte15对应的ASCII码";
CM_ SG_ 2416176712 S2P_Cfg2_SW_Ver_Byte16_08 "SBMU软件版本号最高字节Byte16对应的ASCII码";
CM_ SG_ 2416176713 S2P_Cfg2_SW_Ver_Byte9_09 "SBMU软件版本号Byte9对应的ASCII码";
CM_ SG_ 2416176713 S2P_Cfg2_SW_Ver_Byte10_09 "SBMU软件版本号Byte10对应的ASCII码";
CM_ SG_ 2416176713 S2P_Cfg2_SW_Ver_Byte11_09 "SBMU软件版本号Byte11对应的ASCII码";
CM_ SG_ 2416176713 S2P_Cfg2_SW_Ver_Byte12_09 "SBMU软件版本号Byte12对应的ASCII码";
CM_ SG_ 2416176713 S2P_Cfg2_SW_Ver_Byte13_09 "SBMU软件版本号Byte13对应的ASCII码";
CM_ SG_ 2416176713 S2P_Cfg2_SW_Ver_Byte14_09 "SBMU软件版本号Byte14对应的ASCII码";
CM_ SG_ 2416176713 S2P_Cfg2_SW_Ver_Byte15_09 "SBMU软件版本号Byte15对应的ASCII码";
CM_ SG_ 2416176713 S2P_Cfg2_SW_Ver_Byte16_09 "SBMU软件版本号最高字节Byte16对应的ASCII码";
CM_ SG_ 2416176714 S2P_Cfg2_SW_Ver_Byte9_10 "SBMU软件版本号Byte9对应的ASCII码";
CM_ SG_ 2416176714 S2P_Cfg2_SW_Ver_Byte10_10 "SBMU软件版本号Byte10对应的ASCII码";
CM_ SG_ 2416176714 S2P_Cfg2_SW_Ver_Byte11_10 "SBMU软件版本号Byte11对应的ASCII码";
CM_ SG_ 2416176714 S2P_Cfg2_SW_Ver_Byte12_10 "SBMU软件版本号Byte12对应的ASCII码";
CM_ SG_ 2416176714 S2P_Cfg2_SW_Ver_Byte13_10 "SBMU软件版本号Byte13对应的ASCII码";
CM_ SG_ 2416176714 S2P_Cfg2_SW_Ver_Byte14_10 "SBMU软件版本号Byte14对应的ASCII码";
CM_ SG_ 2416176714 S2P_Cfg2_SW_Ver_Byte15_10 "SBMU软件版本号Byte15对应的ASCII码";
CM_ SG_ 2416176714 S2P_Cfg2_SW_Ver_Byte16_10 "SBMU软件版本号最高字节Byte16对应的ASCII码";
CM_ SG_ 2416176715 S2P_Cfg2_SW_Ver_Byte9_11 "SBMU软件版本号Byte9对应的ASCII码";
CM_ SG_ 2416176715 S2P_Cfg2_SW_Ver_Byte10_11 "SBMU软件版本号Byte10对应的ASCII码";
CM_ SG_ 2416176715 S2P_Cfg2_SW_Ver_Byte11_11 "SBMU软件版本号Byte11对应的ASCII码";
CM_ SG_ 2416176715 S2P_Cfg2_SW_Ver_Byte12_11 "SBMU软件版本号Byte12对应的ASCII码";
CM_ SG_ 2416176715 S2P_Cfg2_SW_Ver_Byte13_11 "SBMU软件版本号Byte13对应的ASCII码";
CM_ SG_ 2416176715 S2P_Cfg2_SW_Ver_Byte14_11 "SBMU软件版本号Byte14对应的ASCII码";
CM_ SG_ 2416176715 S2P_Cfg2_SW_Ver_Byte15_11 "SBMU软件版本号Byte15对应的ASCII码";
CM_ SG_ 2416176715 S2P_Cfg2_SW_Ver_Byte16_11 "SBMU软件版本号最高字节Byte16对应的ASCII码";
CM_ SG_ 2416176716 S2P_Cfg2_SW_Ver_Byte9_12 "SBMU软件版本号Byte9对应的ASCII码";
CM_ SG_ 2416176716 S2P_Cfg2_SW_Ver_Byte10_12 "SBMU软件版本号Byte10对应的ASCII码";
CM_ SG_ 2416176716 S2P_Cfg2_SW_Ver_Byte11_12 "SBMU软件版本号Byte11对应的ASCII码";
CM_ SG_ 2416176716 S2P_Cfg2_SW_Ver_Byte12_12 "SBMU软件版本号Byte12对应的ASCII码";
CM_ SG_ 2416176716 S2P_Cfg2_SW_Ver_Byte13_12 "SBMU软件版本号Byte13对应的ASCII码";
CM_ SG_ 2416176716 S2P_Cfg2_SW_Ver_Byte14_12 "SBMU软件版本号Byte14对应的ASCII码";
CM_ SG_ 2416176716 S2P_Cfg2_SW_Ver_Byte15_12 "SBMU软件版本号Byte15对应的ASCII码";
CM_ SG_ 2416176716 S2P_Cfg2_SW_Ver_Byte16_12 "SBMU软件版本号最高字节Byte16对应的ASCII码";
CM_ SG_ 2416176717 S2P_Cfg2_SW_Ver_Byte9_13 "SBMU软件版本号Byte9对应的ASCII码";
CM_ SG_ 2416176717 S2P_Cfg2_SW_Ver_Byte10_13 "SBMU软件版本号Byte10对应的ASCII码";
CM_ SG_ 2416176717 S2P_Cfg2_SW_Ver_Byte11_13 "SBMU软件版本号Byte11对应的ASCII码";
CM_ SG_ 2416176717 S2P_Cfg2_SW_Ver_Byte12_13 "SBMU软件版本号Byte12对应的ASCII码";
CM_ SG_ 2416176717 S2P_Cfg2_SW_Ver_Byte13_13 "SBMU软件版本号Byte13对应的ASCII码";
CM_ SG_ 2416176717 S2P_Cfg2_SW_Ver_Byte14_13 "SBMU软件版本号Byte14对应的ASCII码";
CM_ SG_ 2416176717 S2P_Cfg2_SW_Ver_Byte15_13 "SBMU软件版本号Byte15对应的ASCII码";
CM_ SG_ 2416176717 S2P_Cfg2_SW_Ver_Byte16_13 "SBMU软件版本号最高字节Byte16对应的ASCII码";
CM_ SG_ 2416176718 S2P_Cfg2_SW_Ver_Byte9_14 "SBMU软件版本号Byte9对应的ASCII码";
CM_ SG_ 2416176718 S2P_Cfg2_SW_Ver_Byte10_14 "SBMU软件版本号Byte10对应的ASCII码";
CM_ SG_ 2416176718 S2P_Cfg2_SW_Ver_Byte11_14 "SBMU软件版本号Byte11对应的ASCII码";
CM_ SG_ 2416176718 S2P_Cfg2_SW_Ver_Byte12_14 "SBMU软件版本号Byte12对应的ASCII码";
CM_ SG_ 2416176718 S2P_Cfg2_SW_Ver_Byte13_14 "SBMU软件版本号Byte13对应的ASCII码";
CM_ SG_ 2416176718 S2P_Cfg2_SW_Ver_Byte14_14 "SBMU软件版本号Byte14对应的ASCII码";
CM_ SG_ 2416176718 S2P_Cfg2_SW_Ver_Byte15_14 "SBMU软件版本号Byte15对应的ASCII码";
CM_ SG_ 2416176718 S2P_Cfg2_SW_Ver_Byte16_14 "SBMU软件版本号最高字节Byte16对应的ASCII码";
CM_ SG_ 2416176719 S2P_Cfg2_SW_Ver_Byte9_15 "SBMU软件版本号Byte9对应的ASCII码";
CM_ SG_ 2416176719 S2P_Cfg2_SW_Ver_Byte10_15 "SBMU软件版本号Byte10对应的ASCII码";
CM_ SG_ 2416176719 S2P_Cfg2_SW_Ver_Byte11_15 "SBMU软件版本号Byte11对应的ASCII码";
CM_ SG_ 2416176719 S2P_Cfg2_SW_Ver_Byte12_15 "SBMU软件版本号Byte12对应的ASCII码";
CM_ SG_ 2416176719 S2P_Cfg2_SW_Ver_Byte13_15 "SBMU软件版本号Byte13对应的ASCII码";
CM_ SG_ 2416176719 S2P_Cfg2_SW_Ver_Byte14_15 "SBMU软件版本号Byte14对应的ASCII码";
CM_ SG_ 2416176719 S2P_Cfg2_SW_Ver_Byte15_15 "SBMU软件版本号Byte15对应的ASCII码";
CM_ SG_ 2416176719 S2P_Cfg2_SW_Ver_Byte16_15 "SBMU软件版本号最高字节Byte16对应的ASCII码";
CM_ SG_ 2416176720 S2P_Cfg2_SW_Ver_Byte9_16 "SBMU软件版本号Byte9对应的ASCII码";
CM_ SG_ 2416176720 S2P_Cfg2_SW_Ver_Byte10_16 "SBMU软件版本号Byte10对应的ASCII码";
CM_ SG_ 2416176720 S2P_Cfg2_SW_Ver_Byte11_16 "SBMU软件版本号Byte11对应的ASCII码";
CM_ SG_ 2416176720 S2P_Cfg2_SW_Ver_Byte12_16 "SBMU软件版本号Byte12对应的ASCII码";
CM_ SG_ 2416176720 S2P_Cfg2_SW_Ver_Byte13_16 "SBMU软件版本号Byte13对应的ASCII码";
CM_ SG_ 2416176720 S2P_Cfg2_SW_Ver_Byte14_16 "SBMU软件版本号Byte14对应的ASCII码";
CM_ SG_ 2416176720 S2P_Cfg2_SW_Ver_Byte15_16 "SBMU软件版本号Byte15对应的ASCII码";
CM_ SG_ 2416176720 S2P_Cfg2_SW_Ver_Byte16_16 "SBMU软件版本号最高字节Byte16对应的ASCII码";
CM_ SG_ 2416176721 S2P_Cfg2_SW_Ver_Byte9_17 "SBMU软件版本号Byte9对应的ASCII码";
CM_ SG_ 2416176721 S2P_Cfg2_SW_Ver_Byte10_17 "SBMU软件版本号Byte10对应的ASCII码";
CM_ SG_ 2416176721 S2P_Cfg2_SW_Ver_Byte11_17 "SBMU软件版本号Byte11对应的ASCII码";
CM_ SG_ 2416176721 S2P_Cfg2_SW_Ver_Byte12_17 "SBMU软件版本号Byte12对应的ASCII码";
CM_ SG_ 2416176721 S2P_Cfg2_SW_Ver_Byte13_17 "SBMU软件版本号Byte13对应的ASCII码";
CM_ SG_ 2416176721 S2P_Cfg2_SW_Ver_Byte14_17 "SBMU软件版本号Byte14对应的ASCII码";
CM_ SG_ 2416176721 S2P_Cfg2_SW_Ver_Byte15_17 "SBMU软件版本号Byte15对应的ASCII码";
CM_ SG_ 2416176721 S2P_Cfg2_SW_Ver_Byte16_17 "SBMU软件版本号最高字节Byte16对应的ASCII码";
CM_ SG_ 2416176722 S2P_Cfg2_SW_Ver_Byte9_18 "SBMU软件版本号Byte9对应的ASCII码";
CM_ SG_ 2416176722 S2P_Cfg2_SW_Ver_Byte10_18 "SBMU软件版本号Byte10对应的ASCII码";
CM_ SG_ 2416176722 S2P_Cfg2_SW_Ver_Byte11_18 "SBMU软件版本号Byte11对应的ASCII码";
CM_ SG_ 2416176722 S2P_Cfg2_SW_Ver_Byte12_18 "SBMU软件版本号Byte12对应的ASCII码";
CM_ SG_ 2416176722 S2P_Cfg2_SW_Ver_Byte13_18 "SBMU软件版本号Byte13对应的ASCII码";
CM_ SG_ 2416176722 S2P_Cfg2_SW_Ver_Byte14_18 "SBMU软件版本号Byte14对应的ASCII码";
CM_ SG_ 2416176722 S2P_Cfg2_SW_Ver_Byte15_18 "SBMU软件版本号Byte15对应的ASCII码";
CM_ SG_ 2416176722 S2P_Cfg2_SW_Ver_Byte16_18 "SBMU软件版本号最高字节Byte16对应的ASCII码";
CM_ SG_ 2416176723 S2P_Cfg2_SW_Ver_Byte9_19 "SBMU软件版本号Byte9对应的ASCII码";
CM_ SG_ 2416176723 S2P_Cfg2_SW_Ver_Byte10_19 "SBMU软件版本号Byte10对应的ASCII码";
CM_ SG_ 2416176723 S2P_Cfg2_SW_Ver_Byte11_19 "SBMU软件版本号Byte11对应的ASCII码";
CM_ SG_ 2416176723 S2P_Cfg2_SW_Ver_Byte12_19 "SBMU软件版本号Byte12对应的ASCII码";
CM_ SG_ 2416176723 S2P_Cfg2_SW_Ver_Byte13_19 "SBMU软件版本号Byte13对应的ASCII码";
CM_ SG_ 2416176723 S2P_Cfg2_SW_Ver_Byte14_19 "SBMU软件版本号Byte14对应的ASCII码";
CM_ SG_ 2416176723 S2P_Cfg2_SW_Ver_Byte15_19 "SBMU软件版本号Byte15对应的ASCII码";
CM_ SG_ 2416176723 S2P_Cfg2_SW_Ver_Byte16_19 "SBMU软件版本号最高字节Byte16对应的ASCII码";
CM_ SG_ 2416176724 S2P_Cfg2_SW_Ver_Byte9_20 "SBMU软件版本号Byte9对应的ASCII码";
CM_ SG_ 2416176724 S2P_Cfg2_SW_Ver_Byte10_20 "SBMU软件版本号Byte10对应的ASCII码";
CM_ SG_ 2416176724 S2P_Cfg2_SW_Ver_Byte11_20 "SBMU软件版本号Byte11对应的ASCII码";
CM_ SG_ 2416176724 S2P_Cfg2_SW_Ver_Byte12_20 "SBMU软件版本号Byte12对应的ASCII码";
CM_ SG_ 2416176724 S2P_Cfg2_SW_Ver_Byte13_20 "SBMU软件版本号Byte13对应的ASCII码";
CM_ SG_ 2416176724 S2P_Cfg2_SW_Ver_Byte14_20 "SBMU软件版本号Byte14对应的ASCII码";
CM_ SG_ 2416176724 S2P_Cfg2_SW_Ver_Byte15_20 "SBMU软件版本号Byte15对应的ASCII码";
CM_ SG_ 2416176724 S2P_Cfg2_SW_Ver_Byte16_20 "SBMU软件版本号最高字节Byte16对应的ASCII码";
CM_ SG_ 2416176725 S2P_Cfg2_SW_Ver_Byte9_21 "SBMU软件版本号Byte9对应的ASCII码";
CM_ SG_ 2416176725 S2P_Cfg2_SW_Ver_Byte10_21 "SBMU软件版本号Byte10对应的ASCII码";
CM_ SG_ 2416176725 S2P_Cfg2_SW_Ver_Byte11_21 "SBMU软件版本号Byte11对应的ASCII码";
CM_ SG_ 2416176725 S2P_Cfg2_SW_Ver_Byte12_21 "SBMU软件版本号Byte12对应的ASCII码";
CM_ SG_ 2416176725 S2P_Cfg2_SW_Ver_Byte13_21 "SBMU软件版本号Byte13对应的ASCII码";
CM_ SG_ 2416176725 S2P_Cfg2_SW_Ver_Byte14_21 "SBMU软件版本号Byte14对应的ASCII码";
CM_ SG_ 2416176725 S2P_Cfg2_SW_Ver_Byte15_21 "SBMU软件版本号Byte15对应的ASCII码";
CM_ SG_ 2416176725 S2P_Cfg2_SW_Ver_Byte16_21 "SBMU软件版本号最高字节Byte16对应的ASCII码";
CM_ SG_ 2416176726 S2P_Cfg2_SW_Ver_Byte9_22 "SBMU软件版本号Byte9对应的ASCII码";
CM_ SG_ 2416176726 S2P_Cfg2_SW_Ver_Byte10_22 "SBMU软件版本号Byte10对应的ASCII码";
CM_ SG_ 2416176726 S2P_Cfg2_SW_Ver_Byte11_22 "SBMU软件版本号Byte11对应的ASCII码";
CM_ SG_ 2416176726 S2P_Cfg2_SW_Ver_Byte12_22 "SBMU软件版本号Byte12对应的ASCII码";
CM_ SG_ 2416176726 S2P_Cfg2_SW_Ver_Byte13_22 "SBMU软件版本号Byte13对应的ASCII码";
CM_ SG_ 2416176726 S2P_Cfg2_SW_Ver_Byte14_22 "SBMU软件版本号Byte14对应的ASCII码";
CM_ SG_ 2416176726 S2P_Cfg2_SW_Ver_Byte15_22 "SBMU软件版本号Byte15对应的ASCII码";
CM_ SG_ 2416176726 S2P_Cfg2_SW_Ver_Byte16_22 "SBMU软件版本号最高字节Byte16对应的ASCII码";
CM_ SG_ 2416176727 S2P_Cfg2_SW_Ver_Byte9_23 "SBMU软件版本号Byte9对应的ASCII码";
CM_ SG_ 2416176727 S2P_Cfg2_SW_Ver_Byte10_23 "SBMU软件版本号Byte10对应的ASCII码";
CM_ SG_ 2416176727 S2P_Cfg2_SW_Ver_Byte11_23 "SBMU软件版本号Byte11对应的ASCII码";
CM_ SG_ 2416176727 S2P_Cfg2_SW_Ver_Byte12_23 "SBMU软件版本号Byte12对应的ASCII码";
CM_ SG_ 2416176727 S2P_Cfg2_SW_Ver_Byte13_23 "SBMU软件版本号Byte13对应的ASCII码";
CM_ SG_ 2416176727 S2P_Cfg2_SW_Ver_Byte14_23 "SBMU软件版本号Byte14对应的ASCII码";
CM_ SG_ 2416176727 S2P_Cfg2_SW_Ver_Byte15_23 "SBMU软件版本号Byte15对应的ASCII码";
CM_ SG_ 2416176727 S2P_Cfg2_SW_Ver_Byte16_23 "SBMU软件版本号最高字节Byte16对应的ASCII码";
CM_ SG_ 2416176728 S2P_Cfg2_SW_Ver_Byte9_24 "SBMU软件版本号Byte9对应的ASCII码";
CM_ SG_ 2416176728 S2P_Cfg2_SW_Ver_Byte10_24 "SBMU软件版本号Byte10对应的ASCII码";
CM_ SG_ 2416176728 S2P_Cfg2_SW_Ver_Byte11_24 "SBMU软件版本号Byte11对应的ASCII码";
CM_ SG_ 2416176728 S2P_Cfg2_SW_Ver_Byte12_24 "SBMU软件版本号Byte12对应的ASCII码";
CM_ SG_ 2416176728 S2P_Cfg2_SW_Ver_Byte13_24 "SBMU软件版本号Byte13对应的ASCII码";
CM_ SG_ 2416176728 S2P_Cfg2_SW_Ver_Byte14_24 "SBMU软件版本号Byte14对应的ASCII码";
CM_ SG_ 2416176728 S2P_Cfg2_SW_Ver_Byte15_24 "SBMU软件版本号Byte15对应的ASCII码";
CM_ SG_ 2416176728 S2P_Cfg2_SW_Ver_Byte16_24 "SBMU软件版本号最高字节Byte16对应的ASCII码";
CM_ SG_ 2416176729 S2P_Cfg2_SW_Ver_Byte9_25 "SBMU软件版本号Byte9对应的ASCII码";
CM_ SG_ 2416176729 S2P_Cfg2_SW_Ver_Byte10_25 "SBMU软件版本号Byte10对应的ASCII码";
CM_ SG_ 2416176729 S2P_Cfg2_SW_Ver_Byte11_25 "SBMU软件版本号Byte11对应的ASCII码";
CM_ SG_ 2416176729 S2P_Cfg2_SW_Ver_Byte12_25 "SBMU软件版本号Byte12对应的ASCII码";
CM_ SG_ 2416176729 S2P_Cfg2_SW_Ver_Byte13_25 "SBMU软件版本号Byte13对应的ASCII码";
CM_ SG_ 2416176729 S2P_Cfg2_SW_Ver_Byte14_25 "SBMU软件版本号Byte14对应的ASCII码";
CM_ SG_ 2416176729 S2P_Cfg2_SW_Ver_Byte15_25 "SBMU软件版本号Byte15对应的ASCII码";
CM_ SG_ 2416176729 S2P_Cfg2_SW_Ver_Byte16_25 "SBMU软件版本号最高字节Byte16对应的ASCII码";
CM_ SG_ 2416176730 S2P_Cfg2_SW_Ver_Byte9_26 "SBMU软件版本号Byte9对应的ASCII码";
CM_ SG_ 2416176730 S2P_Cfg2_SW_Ver_Byte10_26 "SBMU软件版本号Byte10对应的ASCII码";
CM_ SG_ 2416176730 S2P_Cfg2_SW_Ver_Byte11_26 "SBMU软件版本号Byte11对应的ASCII码";
CM_ SG_ 2416176730 S2P_Cfg2_SW_Ver_Byte12_26 "SBMU软件版本号Byte12对应的ASCII码";
CM_ SG_ 2416176730 S2P_Cfg2_SW_Ver_Byte13_26 "SBMU软件版本号Byte13对应的ASCII码";
CM_ SG_ 2416176730 S2P_Cfg2_SW_Ver_Byte14_26 "SBMU软件版本号Byte14对应的ASCII码";
CM_ SG_ 2416176730 S2P_Cfg2_SW_Ver_Byte15_26 "SBMU软件版本号Byte15对应的ASCII码";
CM_ SG_ 2416176730 S2P_Cfg2_SW_Ver_Byte16_26 "SBMU软件版本号最高字节Byte16对应的ASCII码";
CM_ SG_ 2416176731 S2P_Cfg2_SW_Ver_Byte9_27 "SBMU软件版本号Byte9对应的ASCII码";
CM_ SG_ 2416176731 S2P_Cfg2_SW_Ver_Byte10_27 "SBMU软件版本号Byte10对应的ASCII码";
CM_ SG_ 2416176731 S2P_Cfg2_SW_Ver_Byte11_27 "SBMU软件版本号Byte11对应的ASCII码";
CM_ SG_ 2416176731 S2P_Cfg2_SW_Ver_Byte12_27 "SBMU软件版本号Byte12对应的ASCII码";
CM_ SG_ 2416176731 S2P_Cfg2_SW_Ver_Byte13_27 "SBMU软件版本号Byte13对应的ASCII码";
CM_ SG_ 2416176731 S2P_Cfg2_SW_Ver_Byte14_27 "SBMU软件版本号Byte14对应的ASCII码";
CM_ SG_ 2416176731 S2P_Cfg2_SW_Ver_Byte15_27 "SBMU软件版本号Byte15对应的ASCII码";
CM_ SG_ 2416176731 S2P_Cfg2_SW_Ver_Byte16_27 "SBMU软件版本号最高字节Byte16对应的ASCII码";
CM_ SG_ 2416176732 S2P_Cfg2_SW_Ver_Byte9_28 "SBMU软件版本号Byte9对应的ASCII码";
CM_ SG_ 2416176732 S2P_Cfg2_SW_Ver_Byte10_28 "SBMU软件版本号Byte10对应的ASCII码";
CM_ SG_ 2416176732 S2P_Cfg2_SW_Ver_Byte11_28 "SBMU软件版本号Byte11对应的ASCII码";
CM_ SG_ 2416176732 S2P_Cfg2_SW_Ver_Byte12_28 "SBMU软件版本号Byte12对应的ASCII码";
CM_ SG_ 2416176732 S2P_Cfg2_SW_Ver_Byte13_28 "SBMU软件版本号Byte13对应的ASCII码";
CM_ SG_ 2416176732 S2P_Cfg2_SW_Ver_Byte14_28 "SBMU软件版本号Byte14对应的ASCII码";
CM_ SG_ 2416176732 S2P_Cfg2_SW_Ver_Byte15_28 "SBMU软件版本号Byte15对应的ASCII码";
CM_ SG_ 2416176732 S2P_Cfg2_SW_Ver_Byte16_28 "SBMU软件版本号最高字节Byte16对应的ASCII码";
CM_ SG_ 2416176733 S2P_Cfg2_SW_Ver_Byte9_29 "SBMU软件版本号Byte9对应的ASCII码";
CM_ SG_ 2416176733 S2P_Cfg2_SW_Ver_Byte10_29 "SBMU软件版本号Byte10对应的ASCII码";
CM_ SG_ 2416176733 S2P_Cfg2_SW_Ver_Byte11_29 "SBMU软件版本号Byte11对应的ASCII码";
CM_ SG_ 2416176733 S2P_Cfg2_SW_Ver_Byte12_29 "SBMU软件版本号Byte12对应的ASCII码";
CM_ SG_ 2416176733 S2P_Cfg2_SW_Ver_Byte13_29 "SBMU软件版本号Byte13对应的ASCII码";
CM_ SG_ 2416176733 S2P_Cfg2_SW_Ver_Byte14_29 "SBMU软件版本号Byte14对应的ASCII码";
CM_ SG_ 2416176733 S2P_Cfg2_SW_Ver_Byte15_29 "SBMU软件版本号Byte15对应的ASCII码";
CM_ SG_ 2416176733 S2P_Cfg2_SW_Ver_Byte16_29 "SBMU软件版本号最高字节Byte16对应的ASCII码";
CM_ SG_ 2416176734 S2P_Cfg2_SW_Ver_Byte9_30 "SBMU软件版本号Byte9对应的ASCII码";
CM_ SG_ 2416176734 S2P_Cfg2_SW_Ver_Byte10_30 "SBMU软件版本号Byte10对应的ASCII码";
CM_ SG_ 2416176734 S2P_Cfg2_SW_Ver_Byte11_30 "SBMU软件版本号Byte11对应的ASCII码";
CM_ SG_ 2416176734 S2P_Cfg2_SW_Ver_Byte12_30 "SBMU软件版本号Byte12对应的ASCII码";
CM_ SG_ 2416176734 S2P_Cfg2_SW_Ver_Byte13_30 "SBMU软件版本号Byte13对应的ASCII码";
CM_ SG_ 2416176734 S2P_Cfg2_SW_Ver_Byte14_30 "SBMU软件版本号Byte14对应的ASCII码";
CM_ SG_ 2416176734 S2P_Cfg2_SW_Ver_Byte15_30 "SBMU软件版本号Byte15对应的ASCII码";
CM_ SG_ 2416176734 S2P_Cfg2_SW_Ver_Byte16_30 "SBMU软件版本号最高字节Byte16对应的ASCII码";
CM_ SG_ 2416176735 S2P_Cfg2_SW_Ver_Byte9_31 "SBMU软件版本号Byte9对应的ASCII码";
CM_ SG_ 2416176735 S2P_Cfg2_SW_Ver_Byte10_31 "SBMU软件版本号Byte10对应的ASCII码";
CM_ SG_ 2416176735 S2P_Cfg2_SW_Ver_Byte11_31 "SBMU软件版本号Byte11对应的ASCII码";
CM_ SG_ 2416176735 S2P_Cfg2_SW_Ver_Byte12_31 "SBMU软件版本号Byte12对应的ASCII码";
CM_ SG_ 2416176735 S2P_Cfg2_SW_Ver_Byte13_31 "SBMU软件版本号Byte13对应的ASCII码";
CM_ SG_ 2416176735 S2P_Cfg2_SW_Ver_Byte14_31 "SBMU软件版本号Byte14对应的ASCII码";
CM_ SG_ 2416176735 S2P_Cfg2_SW_Ver_Byte15_31 "SBMU软件版本号Byte15对应的ASCII码";
CM_ SG_ 2416176735 S2P_Cfg2_SW_Ver_Byte16_31 "SBMU软件版本号最高字节Byte16对应的ASCII码";
CM_ SG_ 2416176736 S2P_Cfg2_SW_Ver_Byte9_32 "SBMU软件版本号Byte9对应的ASCII码";
CM_ SG_ 2416176736 S2P_Cfg2_SW_Ver_Byte10_32 "SBMU软件版本号Byte10对应的ASCII码";
CM_ SG_ 2416176736 S2P_Cfg2_SW_Ver_Byte11_32 "SBMU软件版本号Byte11对应的ASCII码";
CM_ SG_ 2416176736 S2P_Cfg2_SW_Ver_Byte12_32 "SBMU软件版本号Byte12对应的ASCII码";
CM_ SG_ 2416176736 S2P_Cfg2_SW_Ver_Byte13_32 "SBMU软件版本号Byte13对应的ASCII码";
CM_ SG_ 2416176736 S2P_Cfg2_SW_Ver_Byte14_32 "SBMU软件版本号Byte14对应的ASCII码";
CM_ SG_ 2416176736 S2P_Cfg2_SW_Ver_Byte15_32 "SBMU软件版本号Byte15对应的ASCII码";
CM_ SG_ 2416176736 S2P_Cfg2_SW_Ver_Byte16_32 "SBMU软件版本号最高字节Byte16对应的ASCII码";
CM_ SG_ 2416176737 S2P_Cfg2_SW_Ver_Byte9_33 "SBMU软件版本号Byte9对应的ASCII码";
CM_ SG_ 2416176737 S2P_Cfg2_SW_Ver_Byte10_33 "SBMU软件版本号Byte10对应的ASCII码";
CM_ SG_ 2416176737 S2P_Cfg2_SW_Ver_Byte11_33 "SBMU软件版本号Byte11对应的ASCII码";
CM_ SG_ 2416176737 S2P_Cfg2_SW_Ver_Byte12_33 "SBMU软件版本号Byte12对应的ASCII码";
CM_ SG_ 2416176737 S2P_Cfg2_SW_Ver_Byte13_33 "SBMU软件版本号Byte13对应的ASCII码";
CM_ SG_ 2416176737 S2P_Cfg2_SW_Ver_Byte14_33 "SBMU软件版本号Byte14对应的ASCII码";
CM_ SG_ 2416176737 S2P_Cfg2_SW_Ver_Byte15_33 "SBMU软件版本号Byte15对应的ASCII码";
CM_ SG_ 2416176737 S2P_Cfg2_SW_Ver_Byte16_33 "SBMU软件版本号最高字节Byte16对应的ASCII码";
CM_ SG_ 2416176738 S2P_Cfg2_SW_Ver_Byte9_34 "SBMU软件版本号Byte9对应的ASCII码";
CM_ SG_ 2416176738 S2P_Cfg2_SW_Ver_Byte10_34 "SBMU软件版本号Byte10对应的ASCII码";
CM_ SG_ 2416176738 S2P_Cfg2_SW_Ver_Byte11_34 "SBMU软件版本号Byte11对应的ASCII码";
CM_ SG_ 2416176738 S2P_Cfg2_SW_Ver_Byte12_34 "SBMU软件版本号Byte12对应的ASCII码";
CM_ SG_ 2416176738 S2P_Cfg2_SW_Ver_Byte13_34 "SBMU软件版本号Byte13对应的ASCII码";
CM_ SG_ 2416176738 S2P_Cfg2_SW_Ver_Byte14_34 "SBMU软件版本号Byte14对应的ASCII码";
CM_ SG_ 2416176738 S2P_Cfg2_SW_Ver_Byte15_34 "SBMU软件版本号Byte15对应的ASCII码";
CM_ SG_ 2416176738 S2P_Cfg2_SW_Ver_Byte16_34 "SBMU软件版本号最高字节Byte16对应的ASCII码";
CM_ SG_ 2416176739 S2P_Cfg2_SW_Ver_Byte9_35 "SBMU软件版本号Byte9对应的ASCII码";
CM_ SG_ 2416176739 S2P_Cfg2_SW_Ver_Byte10_35 "SBMU软件版本号Byte10对应的ASCII码";
CM_ SG_ 2416176739 S2P_Cfg2_SW_Ver_Byte11_35 "SBMU软件版本号Byte11对应的ASCII码";
CM_ SG_ 2416176739 S2P_Cfg2_SW_Ver_Byte12_35 "SBMU软件版本号Byte12对应的ASCII码";
CM_ SG_ 2416176739 S2P_Cfg2_SW_Ver_Byte13_35 "SBMU软件版本号Byte13对应的ASCII码";
CM_ SG_ 2416176739 S2P_Cfg2_SW_Ver_Byte14_35 "SBMU软件版本号Byte14对应的ASCII码";
CM_ SG_ 2416176739 S2P_Cfg2_SW_Ver_Byte15_35 "SBMU软件版本号Byte15对应的ASCII码";
CM_ SG_ 2416176739 S2P_Cfg2_SW_Ver_Byte16_35 "SBMU软件版本号最高字节Byte16对应的ASCII码";
CM_ SG_ 2416176740 S2P_Cfg2_SW_Ver_Byte9_36 "SBMU软件版本号Byte9对应的ASCII码";
CM_ SG_ 2416176740 S2P_Cfg2_SW_Ver_Byte10_36 "SBMU软件版本号Byte10对应的ASCII码";
CM_ SG_ 2416176740 S2P_Cfg2_SW_Ver_Byte11_36 "SBMU软件版本号Byte11对应的ASCII码";
CM_ SG_ 2416176740 S2P_Cfg2_SW_Ver_Byte12_36 "SBMU软件版本号Byte12对应的ASCII码";
CM_ SG_ 2416176740 S2P_Cfg2_SW_Ver_Byte13_36 "SBMU软件版本号Byte13对应的ASCII码";
CM_ SG_ 2416176740 S2P_Cfg2_SW_Ver_Byte14_36 "SBMU软件版本号Byte14对应的ASCII码";
CM_ SG_ 2416176740 S2P_Cfg2_SW_Ver_Byte15_36 "SBMU软件版本号Byte15对应的ASCII码";
CM_ SG_ 2416176740 S2P_Cfg2_SW_Ver_Byte16_36 "SBMU软件版本号最高字节Byte16对应的ASCII码";
CM_ SG_ 2416176741 S2P_Cfg2_SW_Ver_Byte9_37 "SBMU软件版本号Byte9对应的ASCII码";
CM_ SG_ 2416176741 S2P_Cfg2_SW_Ver_Byte10_37 "SBMU软件版本号Byte10对应的ASCII码";
CM_ SG_ 2416176741 S2P_Cfg2_SW_Ver_Byte11_37 "SBMU软件版本号Byte11对应的ASCII码";
CM_ SG_ 2416176741 S2P_Cfg2_SW_Ver_Byte12_37 "SBMU软件版本号Byte12对应的ASCII码";
CM_ SG_ 2416176741 S2P_Cfg2_SW_Ver_Byte13_37 "SBMU软件版本号Byte13对应的ASCII码";
CM_ SG_ 2416176741 S2P_Cfg2_SW_Ver_Byte14_37 "SBMU软件版本号Byte14对应的ASCII码";
CM_ SG_ 2416176741 S2P_Cfg2_SW_Ver_Byte15_37 "SBMU软件版本号Byte15对应的ASCII码";
CM_ SG_ 2416176741 S2P_Cfg2_SW_Ver_Byte16_37 "SBMU软件版本号最高字节Byte16对应的ASCII码";
CM_ SG_ 2416176742 S2P_Cfg2_SW_Ver_Byte9_38 "SBMU软件版本号Byte9对应的ASCII码";
CM_ SG_ 2416176742 S2P_Cfg2_SW_Ver_Byte10_38 "SBMU软件版本号Byte10对应的ASCII码";
CM_ SG_ 2416176742 S2P_Cfg2_SW_Ver_Byte11_38 "SBMU软件版本号Byte11对应的ASCII码";
CM_ SG_ 2416176742 S2P_Cfg2_SW_Ver_Byte12_38 "SBMU软件版本号Byte12对应的ASCII码";
CM_ SG_ 2416176742 S2P_Cfg2_SW_Ver_Byte13_38 "SBMU软件版本号Byte13对应的ASCII码";
CM_ SG_ 2416176742 S2P_Cfg2_SW_Ver_Byte14_38 "SBMU软件版本号Byte14对应的ASCII码";
CM_ SG_ 2416176742 S2P_Cfg2_SW_Ver_Byte15_38 "SBMU软件版本号Byte15对应的ASCII码";
CM_ SG_ 2416176742 S2P_Cfg2_SW_Ver_Byte16_38 "SBMU软件版本号最高字节Byte16对应的ASCII码";
CM_ SG_ 2416176743 S2P_Cfg2_SW_Ver_Byte9_39 "SBMU软件版本号Byte9对应的ASCII码";
CM_ SG_ 2416176743 S2P_Cfg2_SW_Ver_Byte10_39 "SBMU软件版本号Byte10对应的ASCII码";
CM_ SG_ 2416176743 S2P_Cfg2_SW_Ver_Byte11_39 "SBMU软件版本号Byte11对应的ASCII码";
CM_ SG_ 2416176743 S2P_Cfg2_SW_Ver_Byte12_39 "SBMU软件版本号Byte12对应的ASCII码";
CM_ SG_ 2416176743 S2P_Cfg2_SW_Ver_Byte13_39 "SBMU软件版本号Byte13对应的ASCII码";
CM_ SG_ 2416176743 S2P_Cfg2_SW_Ver_Byte14_39 "SBMU软件版本号Byte14对应的ASCII码";
CM_ SG_ 2416176743 S2P_Cfg2_SW_Ver_Byte15_39 "SBMU软件版本号Byte15对应的ASCII码";
CM_ SG_ 2416176743 S2P_Cfg2_SW_Ver_Byte16_39 "SBMU软件版本号最高字节Byte16对应的ASCII码";
CM_ SG_ 2416176744 S2P_Cfg2_SW_Ver_Byte9_40 "SBMU软件版本号Byte9对应的ASCII码";
CM_ SG_ 2416176744 S2P_Cfg2_SW_Ver_Byte10_40 "SBMU软件版本号Byte10对应的ASCII码";
CM_ SG_ 2416176744 S2P_Cfg2_SW_Ver_Byte11_40 "SBMU软件版本号Byte11对应的ASCII码";
CM_ SG_ 2416176744 S2P_Cfg2_SW_Ver_Byte12_40 "SBMU软件版本号Byte12对应的ASCII码";
CM_ SG_ 2416176744 S2P_Cfg2_SW_Ver_Byte13_40 "SBMU软件版本号Byte13对应的ASCII码";
CM_ SG_ 2416176744 S2P_Cfg2_SW_Ver_Byte14_40 "SBMU软件版本号Byte14对应的ASCII码";
CM_ SG_ 2416176744 S2P_Cfg2_SW_Ver_Byte15_40 "SBMU软件版本号Byte15对应的ASCII码";
CM_ SG_ 2416176744 S2P_Cfg2_SW_Ver_Byte16_40 "SBMU软件版本号最高字节Byte16对应的ASCII码";
CM_ SG_ 2416176745 S2P_Cfg2_SW_Ver_Byte9_41 "SBMU软件版本号Byte9对应的ASCII码";
CM_ SG_ 2416176745 S2P_Cfg2_SW_Ver_Byte10_41 "SBMU软件版本号Byte10对应的ASCII码";
CM_ SG_ 2416176745 S2P_Cfg2_SW_Ver_Byte11_41 "SBMU软件版本号Byte11对应的ASCII码";
CM_ SG_ 2416176745 S2P_Cfg2_SW_Ver_Byte12_41 "SBMU软件版本号Byte12对应的ASCII码";
CM_ SG_ 2416176745 S2P_Cfg2_SW_Ver_Byte13_41 "SBMU软件版本号Byte13对应的ASCII码";
CM_ SG_ 2416176745 S2P_Cfg2_SW_Ver_Byte14_41 "SBMU软件版本号Byte14对应的ASCII码";
CM_ SG_ 2416176745 S2P_Cfg2_SW_Ver_Byte15_41 "SBMU软件版本号Byte15对应的ASCII码";
CM_ SG_ 2416176745 S2P_Cfg2_SW_Ver_Byte16_41 "SBMU软件版本号最高字节Byte16对应的ASCII码";
CM_ SG_ 2416176746 S2P_Cfg2_SW_Ver_Byte9_42 "SBMU软件版本号Byte9对应的ASCII码";
CM_ SG_ 2416176746 S2P_Cfg2_SW_Ver_Byte10_42 "SBMU软件版本号Byte10对应的ASCII码";
CM_ SG_ 2416176746 S2P_Cfg2_SW_Ver_Byte11_42 "SBMU软件版本号Byte11对应的ASCII码";
CM_ SG_ 2416176746 S2P_Cfg2_SW_Ver_Byte12_42 "SBMU软件版本号Byte12对应的ASCII码";
CM_ SG_ 2416176746 S2P_Cfg2_SW_Ver_Byte13_42 "SBMU软件版本号Byte13对应的ASCII码";
CM_ SG_ 2416176746 S2P_Cfg2_SW_Ver_Byte14_42 "SBMU软件版本号Byte14对应的ASCII码";
CM_ SG_ 2416176746 S2P_Cfg2_SW_Ver_Byte15_42 "SBMU软件版本号Byte15对应的ASCII码";
CM_ SG_ 2416176746 S2P_Cfg2_SW_Ver_Byte16_42 "SBMU软件版本号最高字节Byte16对应的ASCII码";
CM_ SG_ 2416176747 S2P_Cfg2_SW_Ver_Byte9_43 "SBMU软件版本号Byte9对应的ASCII码";
CM_ SG_ 2416176747 S2P_Cfg2_SW_Ver_Byte10_43 "SBMU软件版本号Byte10对应的ASCII码";
CM_ SG_ 2416176747 S2P_Cfg2_SW_Ver_Byte11_43 "SBMU软件版本号Byte11对应的ASCII码";
CM_ SG_ 2416176747 S2P_Cfg2_SW_Ver_Byte12_43 "SBMU软件版本号Byte12对应的ASCII码";
CM_ SG_ 2416176747 S2P_Cfg2_SW_Ver_Byte13_43 "SBMU软件版本号Byte13对应的ASCII码";
CM_ SG_ 2416176747 S2P_Cfg2_SW_Ver_Byte14_43 "SBMU软件版本号Byte14对应的ASCII码";
CM_ SG_ 2416176747 S2P_Cfg2_SW_Ver_Byte15_43 "SBMU软件版本号Byte15对应的ASCII码";
CM_ SG_ 2416176747 S2P_Cfg2_SW_Ver_Byte16_43 "SBMU软件版本号最高字节Byte16对应的ASCII码";
CM_ SG_ 2416176748 S2P_Cfg2_SW_Ver_Byte9_44 "SBMU软件版本号Byte9对应的ASCII码";
CM_ SG_ 2416176748 S2P_Cfg2_SW_Ver_Byte10_44 "SBMU软件版本号Byte10对应的ASCII码";
CM_ SG_ 2416176748 S2P_Cfg2_SW_Ver_Byte11_44 "SBMU软件版本号Byte11对应的ASCII码";
CM_ SG_ 2416176748 S2P_Cfg2_SW_Ver_Byte12_44 "SBMU软件版本号Byte12对应的ASCII码";
CM_ SG_ 2416176748 S2P_Cfg2_SW_Ver_Byte13_44 "SBMU软件版本号Byte13对应的ASCII码";
CM_ SG_ 2416176748 S2P_Cfg2_SW_Ver_Byte14_44 "SBMU软件版本号Byte14对应的ASCII码";
CM_ SG_ 2416176748 S2P_Cfg2_SW_Ver_Byte15_44 "SBMU软件版本号Byte15对应的ASCII码";
CM_ SG_ 2416176748 S2P_Cfg2_SW_Ver_Byte16_44 "SBMU软件版本号最高字节Byte16对应的ASCII码";
CM_ SG_ 2416176749 S2P_Cfg2_SW_Ver_Byte9_45 "SBMU软件版本号Byte9对应的ASCII码";
CM_ SG_ 2416176749 S2P_Cfg2_SW_Ver_Byte10_45 "SBMU软件版本号Byte10对应的ASCII码";
CM_ SG_ 2416176749 S2P_Cfg2_SW_Ver_Byte11_45 "SBMU软件版本号Byte11对应的ASCII码";
CM_ SG_ 2416176749 S2P_Cfg2_SW_Ver_Byte12_45 "SBMU软件版本号Byte12对应的ASCII码";
CM_ SG_ 2416176749 S2P_Cfg2_SW_Ver_Byte13_45 "SBMU软件版本号Byte13对应的ASCII码";
CM_ SG_ 2416176749 S2P_Cfg2_SW_Ver_Byte14_45 "SBMU软件版本号Byte14对应的ASCII码";
CM_ SG_ 2416176749 S2P_Cfg2_SW_Ver_Byte15_45 "SBMU软件版本号Byte15对应的ASCII码";
CM_ SG_ 2416176749 S2P_Cfg2_SW_Ver_Byte16_45 "SBMU软件版本号最高字节Byte16对应的ASCII码";
VERSION ""

NS_ :

BS_:

BU_: MBMU PC SBMU IMM ETH DCDC LEMS

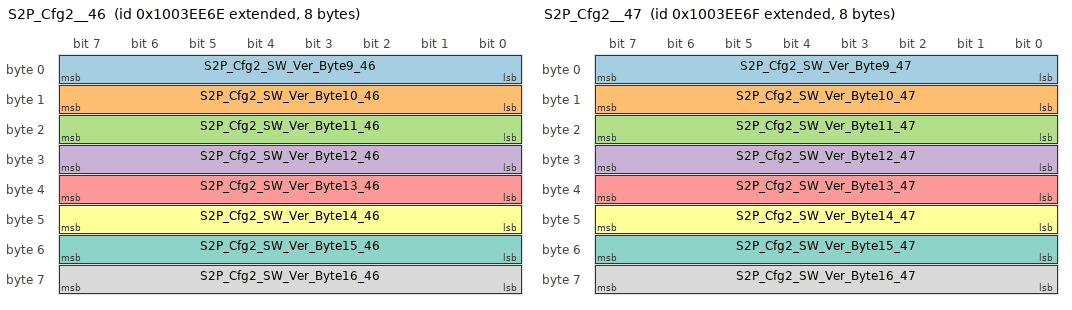
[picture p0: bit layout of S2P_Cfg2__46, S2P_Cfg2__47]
BO_ 2416176750 S2P_Cfg2__46: 8 SBMU
 SG_ S2P_Cfg2_SW_Ver_Byte9_46 : 0|8@1+ (1,0) [0|255] ""  PC
 SG_ S2P_Cfg2_SW_Ver_Byte10_46 : 8|8@1+ (1,0) [0|255] ""  PC
 SG_ S2P_Cfg2_SW_Ver_Byte11_46 : 16|8@1+ (1,0) [0|255] ""  PC
 SG_ S2P_Cfg2_SW_Ver_Byte12_46 : 24|8@1+ (1,0) [0|255] ""  PC
 SG_ S2P_Cfg2_SW_Ver_Byte13_46 : 32|8@1+ (1,0) [0|255] ""  PC
 SG_ S2P_Cfg2_SW_Ver_Byte14_46 : 40|8@1+ (1,0) [0|255] ""  PC
 SG_ S2P_Cfg2_SW_Ver_Byte15_46 : 48|8@1+ (1,0) [0|255] ""  PC
 SG_ S2P_Cfg2_SW_Ver_Byte16_46 : 56|8@1+ (1,0) [0|255] ""  PC

BO_ 2416176751 S2P_Cfg2__47: 8 SBMU
 SG_ S2P_Cfg2_SW_Ver_Byte9_47 : 0|8@1+ (1,0) [0|255] ""  PC
 SG_ S2P_Cfg2_SW_Ver_Byte10_47 : 8|8@1+ (1,0) [0|255] ""  PC
 SG_ S2P_Cfg2_SW_Ver_Byte11_47 : 16|8@1+ (1,0) [0|255] ""  PC
 SG_ S2P_Cfg2_SW_Ver_Byte12_47 : 24|8@1+ (1,0) [0|255] ""  PC
 SG_ S2P_Cfg2_SW_Ver_Byte13_47 : 32|8@1+ (1,0) [0|255] ""  PC
 SG_ S2P_Cfg2_SW_Ver_Byte14_47 : 40|8@1+ (1,0) [0|255] ""  PC
 SG_ S2P_Cfg2_SW_Ver_Byte15_47 : 48|8@1+ (1,0) [0|255] ""  PC
 SG_ S2P_Cfg2_SW_Ver_Byte16_47 : 56|8@1+ (1,0) [0|255] ""  PC

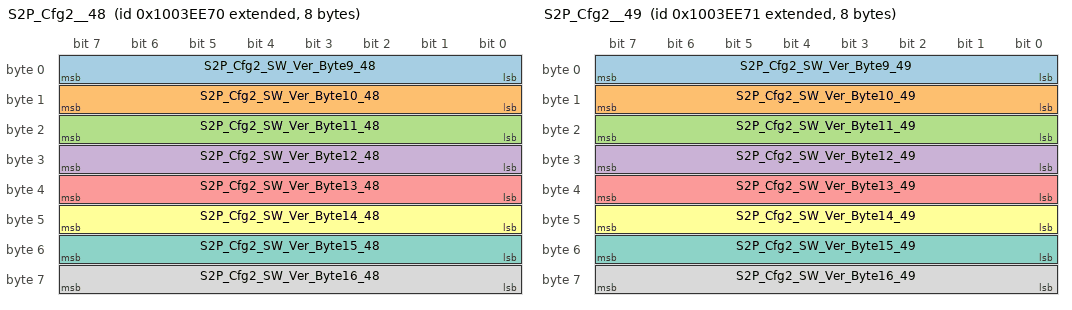
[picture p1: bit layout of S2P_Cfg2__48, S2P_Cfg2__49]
BO_ 2416176752 S2P_Cfg2__48: 8 SBMU
 SG_ S2P_Cfg2_SW_Ver_Byte9_48 : 0|8@1+ (1,0) [0|255] ""  PC
 SG_ S2P_Cfg2_SW_Ver_Byte10_48 : 8|8@1+ (1,0) [0|255] ""  PC
 SG_ S2P_Cfg2_SW_Ver_Byte11_48 : 16|8@1+ (1,0) [0|255] ""  PC
 SG_ S2P_Cfg2_SW_Ver_Byte12_48 : 24|8@1+ (1,0) [0|255] ""  PC
 SG_ S2P_Cfg2_SW_Ver_Byte13_48 : 32|8@1+ (1,0) [0|255] ""  PC
 SG_ S2P_Cfg2_SW_Ver_Byte14_48 : 40|8@1+ (1,0) [0|255] ""  PC
 SG_ S2P_Cfg2_SW_Ver_Byte15_48 : 48|8@1+ (1,0) [0|255] ""  PC
 SG_ S2P_Cfg2_SW_Ver_Byte16_48 : 56|8@1+ (1,0) [0|255] ""  PC

BO_ 2416176753 S2P_Cfg2__49: 8 SBMU
 SG_ S2P_Cfg2_SW_Ver_Byte9_49 : 0|8@1+ (1,0) [0|255] ""  PC
 SG_ S2P_Cfg2_SW_Ver_Byte10_49 : 8|8@1+ (1,0) [0|255] ""  PC
 SG_ S2P_Cfg2_SW_Ver_Byte11_49 : 16|8@1+ (1,0) [0|255] ""  PC
 SG_ S2P_Cfg2_SW_Ver_Byte12_49 : 24|8@1+ (1,0) [0|255] ""  PC
 SG_ S2P_Cfg2_SW_Ver_Byte13_49 : 32|8@1+ (1,0) [0|255] ""  PC
 SG_ S2P_Cfg2_SW_Ver_Byte14_49 : 40|8@1+ (1,0) [0|255] ""  PC
 SG_ S2P_Cfg2_SW_Ver_Byte15_49 : 48|8@1+ (1,0) [0|255] ""  PC
 SG_ S2P_Cfg2_SW_Ver_Byte16_49 : 56|8@1+ (1,0) [0|255] ""  PC

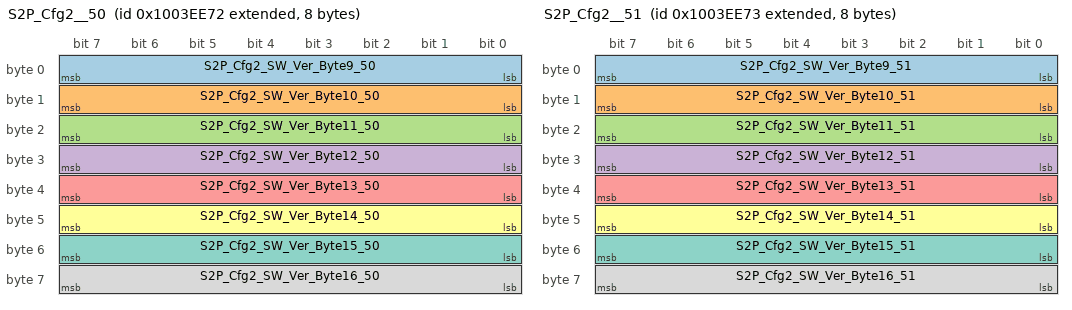
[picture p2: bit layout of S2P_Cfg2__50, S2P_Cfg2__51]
BO_ 2416176754 S2P_Cfg2__50: 8 SBMU
 SG_ S2P_Cfg2_SW_Ver_Byte9_50 : 0|8@1+ (1,0) [0|255] ""  PC
 SG_ S2P_Cfg2_SW_Ver_Byte10_50 : 8|8@1+ (1,0) [0|255] ""  PC
 SG_ S2P_Cfg2_SW_Ver_Byte11_50 : 16|8@1+ (1,0) [0|255] ""  PC
 SG_ S2P_Cfg2_SW_Ver_Byte12_50 : 24|8@1+ (1,0) [0|255] ""  PC
 SG_ S2P_Cfg2_SW_Ver_Byte13_50 : 32|8@1+ (1,0) [0|255] ""  PC
 SG_ S2P_Cfg2_SW_Ver_Byte14_50 : 40|8@1+ (1,0) [0|255] ""  PC
 SG_ S2P_Cfg2_SW_Ver_Byte15_50 : 48|8@1+ (1,0) [0|255] ""  PC
 SG_ S2P_Cfg2_SW_Ver_Byte16_50 : 56|8@1+ (1,0) [0|255] ""  PC

BO_ 2416176755 S2P_Cfg2__51: 8 SBMU
 SG_ S2P_Cfg2_SW_Ver_Byte9_51 : 0|8@1+ (1,0) [0|255] ""  PC
 SG_ S2P_Cfg2_SW_Ver_Byte10_51 : 8|8@1+ (1,0) [0|255] ""  PC
 SG_ S2P_Cfg2_SW_Ver_Byte11_51 : 16|8@1+ (1,0) [0|255] ""  PC
 SG_ S2P_Cfg2_SW_Ver_Byte12_51 : 24|8@1+ (1,0) [0|255] ""  PC
 SG_ S2P_Cfg2_SW_Ver_Byte13_51 : 32|8@1+ (1,0) [0|255] ""  PC
 SG_ S2P_Cfg2_SW_Ver_Byte14_51 : 40|8@1+ (1,0) [0|255] ""  PC
 SG_ S2P_Cfg2_SW_Ver_Byte15_51 : 48|8@1+ (1,0) [0|255] ""  PC
 SG_ S2P_Cfg2_SW_Ver_Byte16_51 : 56|8@1+ (1,0) [0|255] ""  PC

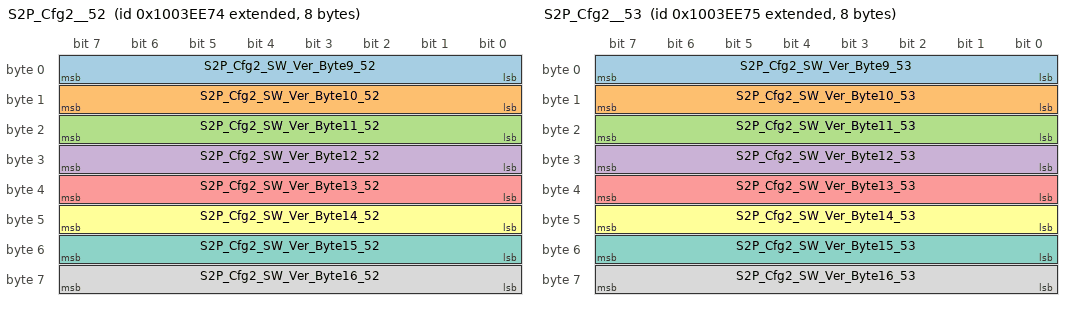
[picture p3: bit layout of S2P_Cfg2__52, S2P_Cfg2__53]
BO_ 2416176756 S2P_Cfg2__52: 8 SBMU
 SG_ S2P_Cfg2_SW_Ver_Byte9_52 : 0|8@1+ (1,0) [0|255] ""  PC
 SG_ S2P_Cfg2_SW_Ver_Byte10_52 : 8|8@1+ (1,0) [0|255] ""  PC
 SG_ S2P_Cfg2_SW_Ver_Byte11_52 : 16|8@1+ (1,0) [0|255] ""  PC
 SG_ S2P_Cfg2_SW_Ver_Byte12_52 : 24|8@1+ (1,0) [0|255] ""  PC
 SG_ S2P_Cfg2_SW_Ver_Byte13_52 : 32|8@1+ (1,0) [0|255] ""  PC
 SG_ S2P_Cfg2_SW_Ver_Byte14_52 : 40|8@1+ (1,0) [0|255] ""  PC
 SG_ S2P_Cfg2_SW_Ver_Byte15_52 : 48|8@1+ (1,0) [0|255] ""  PC
 SG_ S2P_Cfg2_SW_Ver_Byte16_52 : 56|8@1+ (1,0) [0|255] ""  PC

BO_ 2416176757 S2P_Cfg2__53: 8 SBMU
 SG_ S2P_Cfg2_SW_Ver_Byte9_53 : 0|8@1+ (1,0) [0|255] ""  PC
 SG_ S2P_Cfg2_SW_Ver_Byte10_53 : 8|8@1+ (1,0) [0|255] ""  PC
 SG_ S2P_Cfg2_SW_Ver_Byte11_53 : 16|8@1+ (1,0) [0|255] ""  PC
 SG_ S2P_Cfg2_SW_Ver_Byte12_53 : 24|8@1+ (1,0) [0|255] ""  PC
 SG_ S2P_Cfg2_SW_Ver_Byte13_53 : 32|8@1+ (1,0) [0|255] ""  PC
 SG_ S2P_Cfg2_SW_Ver_Byte14_53 : 40|8@1+ (1,0) [0|255] ""  PC
 SG_ S2P_Cfg2_SW_Ver_Byte15_53 : 48|8@1+ (1,0) [0|255] ""  PC
 SG_ S2P_Cfg2_SW_Ver_Byte16_53 : 56|8@1+ (1,0) [0|255] ""  PC

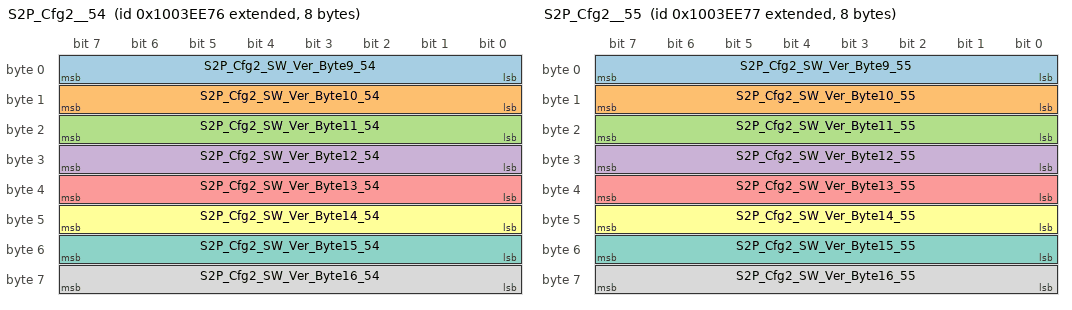
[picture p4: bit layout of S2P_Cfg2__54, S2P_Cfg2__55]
BO_ 2416176758 S2P_Cfg2__54: 8 SBMU
 SG_ S2P_Cfg2_SW_Ver_Byte9_54 : 0|8@1+ (1,0) [0|255] ""  PC
 SG_ S2P_Cfg2_SW_Ver_Byte10_54 : 8|8@1+ (1,0) [0|255] ""  PC
 SG_ S2P_Cfg2_SW_Ver_Byte11_54 : 16|8@1+ (1,0) [0|255] ""  PC
 SG_ S2P_Cfg2_SW_Ver_Byte12_54 : 24|8@1+ (1,0) [0|255] ""  PC
 SG_ S2P_Cfg2_SW_Ver_Byte13_54 : 32|8@1+ (1,0) [0|255] ""  PC
 SG_ S2P_Cfg2_SW_Ver_Byte14_54 : 40|8@1+ (1,0) [0|255] ""  PC
 SG_ S2P_Cfg2_SW_Ver_Byte15_54 : 48|8@1+ (1,0) [0|255] ""  PC
 SG_ S2P_Cfg2_SW_Ver_Byte16_54 : 56|8@1+ (1,0) [0|255] ""  PC

BO_ 2416176759 S2P_Cfg2__55: 8 SBMU
 SG_ S2P_Cfg2_SW_Ver_Byte9_55 : 0|8@1+ (1,0) [0|255] ""  PC
 SG_ S2P_Cfg2_SW_Ver_Byte10_55 : 8|8@1+ (1,0) [0|255] ""  PC
 SG_ S2P_Cfg2_SW_Ver_Byte11_55 : 16|8@1+ (1,0) [0|255] ""  PC
 SG_ S2P_Cfg2_SW_Ver_Byte12_55 : 24|8@1+ (1,0) [0|255] ""  PC
 SG_ S2P_Cfg2_SW_Ver_Byte13_55 : 32|8@1+ (1,0) [0|255] ""  PC
 SG_ S2P_Cfg2_SW_Ver_Byte14_55 : 40|8@1+ (1,0) [0|255] ""  PC
 SG_ S2P_Cfg2_SW_Ver_Byte15_55 : 48|8@1+ (1,0) [0|255] ""  PC
 SG_ S2P_Cfg2_SW_Ver_Byte16_55 : 56|8@1+ (1,0) [0|255] ""  PC

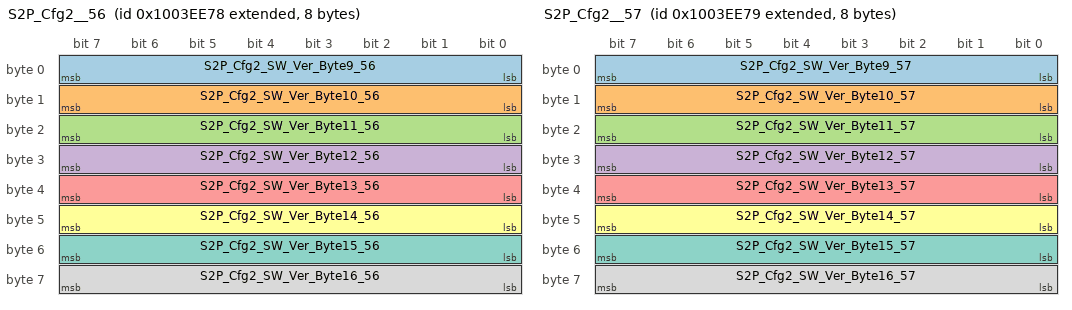
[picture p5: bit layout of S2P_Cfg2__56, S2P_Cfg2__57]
BO_ 2416176760 S2P_Cfg2__56: 8 SBMU
 SG_ S2P_Cfg2_SW_Ver_Byte9_56 : 0|8@1+ (1,0) [0|255] ""  PC
 SG_ S2P_Cfg2_SW_Ver_Byte10_56 : 8|8@1+ (1,0) [0|255] ""  PC
 SG_ S2P_Cfg2_SW_Ver_Byte11_56 : 16|8@1+ (1,0) [0|255] ""  PC
 SG_ S2P_Cfg2_SW_Ver_Byte12_56 : 24|8@1+ (1,0) [0|255] ""  PC
 SG_ S2P_Cfg2_SW_Ver_Byte13_56 : 32|8@1+ (1,0) [0|255] ""  PC
 SG_ S2P_Cfg2_SW_Ver_Byte14_56 : 40|8@1+ (1,0) [0|255] ""  PC
 SG_ S2P_Cfg2_SW_Ver_Byte15_56 : 48|8@1+ (1,0) [0|255] ""  PC
 SG_ S2P_Cfg2_SW_Ver_Byte16_56 : 56|8@1+ (1,0) [0|255] ""  PC

BO_ 2416176761 S2P_Cfg2__57: 8 SBMU
 SG_ S2P_Cfg2_SW_Ver_Byte9_57 : 0|8@1+ (1,0) [0|255] ""  PC
 SG_ S2P_Cfg2_SW_Ver_Byte10_57 : 8|8@1+ (1,0) [0|255] ""  PC
 SG_ S2P_Cfg2_SW_Ver_Byte11_57 : 16|8@1+ (1,0) [0|255] ""  PC
 SG_ S2P_Cfg2_SW_Ver_Byte12_57 : 24|8@1+ (1,0) [0|255] ""  PC
 SG_ S2P_Cfg2_SW_Ver_Byte13_57 : 32|8@1+ (1,0) [0|255] ""  PC
 SG_ S2P_Cfg2_SW_Ver_Byte14_57 : 40|8@1+ (1,0) [0|255] ""  PC
 SG_ S2P_Cfg2_SW_Ver_Byte15_57 : 48|8@1+ (1,0) [0|255] ""  PC
 SG_ S2P_Cfg2_SW_Ver_Byte16_57 : 56|8@1+ (1,0) [0|255] ""  PC

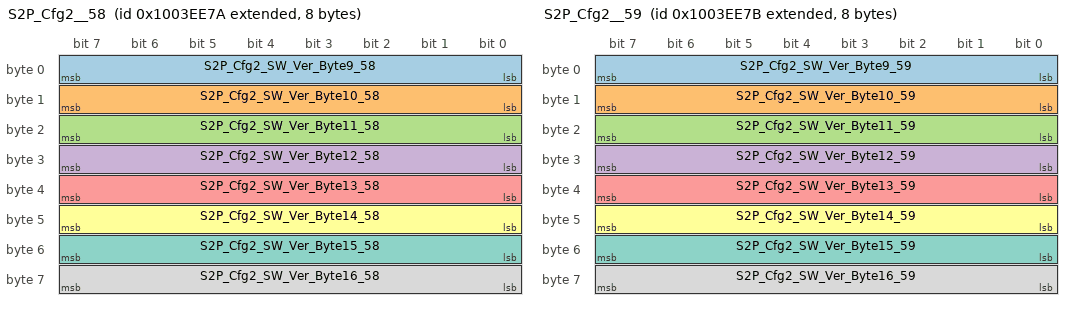
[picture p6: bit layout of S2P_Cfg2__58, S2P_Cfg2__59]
BO_ 2416176762 S2P_Cfg2__58: 8 SBMU
 SG_ S2P_Cfg2_SW_Ver_Byte9_58 : 0|8@1+ (1,0) [0|255] ""  PC
 SG_ S2P_Cfg2_SW_Ver_Byte10_58 : 8|8@1+ (1,0) [0|255] ""  PC
 SG_ S2P_Cfg2_SW_Ver_Byte11_58 : 16|8@1+ (1,0) [0|255] ""  PC
 SG_ S2P_Cfg2_SW_Ver_Byte12_58 : 24|8@1+ (1,0) [0|255] ""  PC
 SG_ S2P_Cfg2_SW_Ver_Byte13_58 : 32|8@1+ (1,0) [0|255] ""  PC
 SG_ S2P_Cfg2_SW_Ver_Byte14_58 : 40|8@1+ (1,0) [0|255] ""  PC
 SG_ S2P_Cfg2_SW_Ver_Byte15_58 : 48|8@1+ (1,0) [0|255] ""  PC
 SG_ S2P_Cfg2_SW_Ver_Byte16_58 : 56|8@1+ (1,0) [0|255] ""  PC

BO_ 2416176763 S2P_Cfg2__59: 8 SBMU
 SG_ S2P_Cfg2_SW_Ver_Byte9_59 : 0|8@1+ (1,0) [0|255] ""  PC
 SG_ S2P_Cfg2_SW_Ver_Byte10_59 : 8|8@1+ (1,0) [0|255] ""  PC
 SG_ S2P_Cfg2_SW_Ver_Byte11_59 : 16|8@1+ (1,0) [0|255] ""  PC
 SG_ S2P_Cfg2_SW_Ver_Byte12_59 : 24|8@1+ (1,0) [0|255] ""  PC
 SG_ S2P_Cfg2_SW_Ver_Byte13_59 : 32|8@1+ (1,0) [0|255] ""  PC
 SG_ S2P_Cfg2_SW_Ver_Byte14_59 : 40|8@1+ (1,0) [0|255] ""  PC
 SG_ S2P_Cfg2_SW_Ver_Byte15_59 : 48|8@1+ (1,0) [0|255] ""  PC
 SG_ S2P_Cfg2_SW_Ver_Byte16_59 : 56|8@1+ (1,0) [0|255] ""  PC

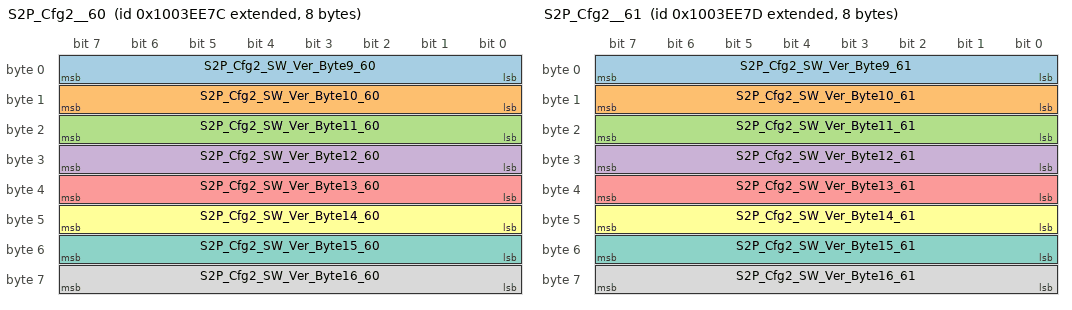
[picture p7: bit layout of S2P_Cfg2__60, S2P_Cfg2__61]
BO_ 2416176764 S2P_Cfg2__60: 8 SBMU
 SG_ S2P_Cfg2_SW_Ver_Byte9_60 : 0|8@1+ (1,0) [0|255] ""  PC
 SG_ S2P_Cfg2_SW_Ver_Byte10_60 : 8|8@1+ (1,0) [0|255] ""  PC
 SG_ S2P_Cfg2_SW_Ver_Byte11_60 : 16|8@1+ (1,0) [0|255] ""  PC
 SG_ S2P_Cfg2_SW_Ver_Byte12_60 : 24|8@1+ (1,0) [0|255] ""  PC
 SG_ S2P_Cfg2_SW_Ver_Byte13_60 : 32|8@1+ (1,0) [0|255] ""  PC
 SG_ S2P_Cfg2_SW_Ver_Byte14_60 : 40|8@1+ (1,0) [0|255] ""  PC
 SG_ S2P_Cfg2_SW_Ver_Byte15_60 : 48|8@1+ (1,0) [0|255] ""  PC
 SG_ S2P_Cfg2_SW_Ver_Byte16_60 : 56|8@1+ (1,0) [0|255] ""  PC

BO_ 2416176765 S2P_Cfg2__61: 8 SBMU
 SG_ S2P_Cfg2_SW_Ver_Byte9_61 : 0|8@1+ (1,0) [0|255] ""  PC
 SG_ S2P_Cfg2_SW_Ver_Byte10_61 : 8|8@1+ (1,0) [0|255] ""  PC
 SG_ S2P_Cfg2_SW_Ver_Byte11_61 : 16|8@1+ (1,0) [0|255] ""  PC
 SG_ S2P_Cfg2_SW_Ver_Byte12_61 : 24|8@1+ (1,0) [0|255] ""  PC
 SG_ S2P_Cfg2_SW_Ver_Byte13_61 : 32|8@1+ (1,0) [0|255] ""  PC
 SG_ S2P_Cfg2_SW_Ver_Byte14_61 : 40|8@1+ (1,0) [0|255] ""  PC
 SG_ S2P_Cfg2_SW_Ver_Byte15_61 : 48|8@1+ (1,0) [0|255] ""  PC
 SG_ S2P_Cfg2_SW_Ver_Byte16_61 : 56|8@1+ (1,0) [0|255] ""  PC

BO_ 2416176766 S2P_Cfg2__62: 8 SBMU
 SG_ S2P_Cfg2_SW_Ver_Byte9_62 : 0|8@1+ (1,0) [0|255] ""  PC
 SG_ S2P_Cfg2_SW_Ver_Byte10_62 : 8|8@1+ (1,0) [0|255] ""  PC
 SG_ S2P_Cfg2_SW_Ver_Byte11_62 : 16|8@1+ (1,0) [0|255] ""  PC
 SG_ S2P_Cfg2_SW_Ver_Byte12_62 : 24|8@1+ (1,0) [0|255] ""  PC
 SG_ S2P_Cfg2_SW_Ver_Byte13_62 : 32|8@1+ (1,0) [0|255] ""  PC
 SG_ S2P_Cfg2_SW_Ver_Byte14_62 : 40|8@1+ (1,0) [0|255] ""  PC
 SG_ S2P_Cfg2_SW_Ver_Byte15_62 : 48|8@1+ (1,0) [0|255] ""  PC
 SG_ S2P_Cfg2_SW_Ver_Byte16_62 : 56|8@1+ (1,0) [0|255] ""  PC

BO_ 2416176767 S2P_Cfg2__63: 8 SBMU
 SG_ S2P_Cfg2_SW_Ver_Byte9_63 : 0|8@1+ (1,0) [0|255] ""  PC
 SG_ S2P_Cfg2_SW_Ver_Byte10_63 : 8|8@1+ (1,0) [0|255] ""  PC
 SG_ S2P_Cfg2_SW_Ver_Byte11_63 : 16|8@1+ (1,0) [0|255] ""  PC
 SG_ S2P_Cfg2_SW_Ver_Byte12_63 : 24|8@1+ (1,0) [0|255] ""  PC
 SG_ S2P_Cfg2_SW_Ver_Byte13_63 : 32|8@1+ (1,0) [0|255] ""  PC
 SG_ S2P_Cfg2_SW_Ver_Byte14_63 : 40|8@1+ (1,0) [0|255] ""  PC
 SG_ S2P_Cfg2_SW_Ver_Byte15_63 : 48|8@1+ (1,0) [0|255] ""  PC
 SG_ S2P_Cfg2_SW_Ver_Byte16_63 : 56|8@1+ (1,0) [0|255] ""  PC

BO_ 2416242241 S2P_Cfg3__01: 8 SBMU
 SG_ S2P_Cfg3_HW_Ver_Byte1_01 : 0|8@1+ (1,0) [0|255] ""  PC
 SG_ S2P_Cfg3_HW_Ver_Byte2_01 : 8|8@1+ (1,0) [0|255] ""  PC
 SG_ S2P_Cfg3_HW_Ver_Byte3_01 : 16|8@1+ (1,0) [0|255] ""  PC
 SG_ S2P_Cfg3_HW_Ver_Byte4_01 : 24|8@1+ (1,0) [0|255] ""  PC
 SG_ S2P_Cfg3_HW_Ver_Byte5_01 : 32|8@1+ (1,0) [0|255] ""  PC
 SG_ S2P_Cfg3_HW_Ver_Byte6_01 : 40|8@1+ (1,0) [0|255] ""  PC
 SG_ S2P_Cfg3_HW_Ver_Byte7_01 : 48|8@1+ (1,0) [0|255] ""  PC
 SG_ S2P_Cfg3_HW_Ver_Byte8_01 : 56|8@1+ (1,0) [0|255] ""  PC

BO_ 2416242242 S2P_Cfg3__02: 8 SBMU
 SG_ S2P_Cfg3_HW_Ver_Byte1_02 : 0|8@1+ (1,0) [0|255] ""  PC
 SG_ S2P_Cfg3_HW_Ver_Byte2_02 : 8|8@1+ (1,0) [0|255] ""  PC
 SG_ S2P_Cfg3_HW_Ver_Byte3_02 : 16|8@1+ (1,0) [0|255] ""  PC
 SG_ S2P_Cfg3_HW_Ver_Byte4_02 : 24|8@1+ (1,0) [0|255] ""  PC
 SG_ S2P_Cfg3_HW_Ver_Byte5_02 : 32|8@1+ (1,0) [0|255] ""  PC
 SG_ S2P_Cfg3_HW_Ver_Byte6_02 : 40|8@1+ (1,0) [0|255] ""  PC
 SG_ S2P_Cfg3_HW_Ver_Byte7_02 : 48|8@1+ (1,0) [0|255] ""  PC
 SG_ S2P_Cfg3_HW_Ver_Byte8_02 : 56|8@1+ (1,0) [0|255] ""  PC

BO_ 2416242243 S2P_Cfg3__03: 8 SBMU
 SG_ S2P_Cfg3_HW_Ver_Byte1_03 : 0|8@1+ (1,0) [0|255] ""  PC
 SG_ S2P_Cfg3_HW_Ver_Byte2_03 : 8|8@1+ (1,0) [0|255] ""  PC
 SG_ S2P_Cfg3_HW_Ver_Byte3_03 : 16|8@1+ (1,0) [0|255] ""  PC
 SG_ S2P_Cfg3_HW_Ver_Byte4_03 : 24|8@1+ (1,0) [0|255] ""  PC
 SG_ S2P_Cfg3_HW_Ver_Byte5_03 : 32|8@1+ (1,0) [0|255] ""  PC
 SG_ S2P_Cfg3_HW_Ver_Byte6_03 : 40|8@1+ (1,0) [0|255] ""  PC
 SG_ S2P_Cfg3_HW_Ver_Byte7_03 : 48|8@1+ (1,0) [0|255] ""  PC
 SG_ S2P_Cfg3_HW_Ver_Byte8_03 : 56|8@1+ (1,0) [0|255] ""  PC

BO_ 2416242244 S2P_Cfg3__04: 8 SBMU
 SG_ S2P_Cfg3_HW_Ver_Byte1_04 : 0|8@1+ (1,0) [0|255] ""  PC
 SG_ S2P_Cfg3_HW_Ver_Byte2_04 : 8|8@1+ (1,0) [0|255] ""  PC
 SG_ S2P_Cfg3_HW_Ver_Byte3_04 : 16|8@1+ (1,0) [0|255] ""  PC
 SG_ S2P_Cfg3_HW_Ver_Byte4_04 : 24|8@1+ (1,0) [0|255] ""  PC
 SG_ S2P_Cfg3_HW_Ver_Byte5_04 : 32|8@1+ (1,0) [0|255] ""  PC
 SG_ S2P_Cfg3_HW_Ver_Byte6_04 : 40|8@1+ (1,0) [0|255] ""  PC
 SG_ S2P_Cfg3_HW_Ver_Byte7_04 : 48|8@1+ (1,0) [0|255] ""  PC
 SG_ S2P_Cfg3_HW_Ver_Byte8_04 : 56|8@1+ (1,0) [0|255] ""  PC

BO_ 2416242245 S2P_Cfg3__05: 8 SBMU
 SG_ S2P_Cfg3_HW_Ver_Byte1_05 : 0|8@1+ (1,0) [0|255] ""  PC
 SG_ S2P_Cfg3_HW_Ver_Byte2_05 : 8|8@1+ (1,0) [0|255] ""  PC
 SG_ S2P_Cfg3_HW_Ver_Byte3_05 : 16|8@1+ (1,0) [0|255] ""  PC
 SG_ S2P_Cfg3_HW_Ver_Byte4_05 : 24|8@1+ (1,0) [0|255] ""  PC
 SG_ S2P_Cfg3_HW_Ver_Byte5_05 : 32|8@1+ (1,0) [0|255] ""  PC
 SG_ S2P_Cfg3_HW_Ver_Byte6_05 : 40|8@1+ (1,0) [0|255] ""  PC
 SG_ S2P_Cfg3_HW_Ver_Byte7_05 : 48|8@1+ (1,0) [0|255] ""  PC
 SG_ S2P_Cfg3_HW_Ver_Byte8_05 : 56|8@1+ (1,0) [0|255] ""  PC

BO_ 2416242246 S2P_Cfg3__06: 8 SBMU
 SG_ S2P_Cfg3_HW_Ver_Byte1_06 : 0|8@1+ (1,0) [0|255] ""  PC
 SG_ S2P_Cfg3_HW_Ver_Byte2_06 : 8|8@1+ (1,0) [0|255] ""  PC
 SG_ S2P_Cfg3_HW_Ver_Byte3_06 : 16|8@1+ (1,0) [0|255] ""  PC
 SG_ S2P_Cfg3_HW_Ver_Byte4_06 : 24|8@1+ (1,0) [0|255] ""  PC
 SG_ S2P_Cfg3_HW_Ver_Byte5_06 : 32|8@1+ (1,0) [0|255] ""  PC
 SG_ S2P_Cfg3_HW_Ver_Byte6_06 : 40|8@1+ (1,0) [0|255] ""  PC
 SG_ S2P_Cfg3_HW_Ver_Byte7_06 : 48|8@1+ (1,0) [0|255] ""  PC
 SG_ S2P_Cfg3_HW_Ver_Byte8_06 : 56|8@1+ (1,0) [0|255] ""  PC

BO_ 2416242247 S2P_Cfg3__07: 8 SBMU
 SG_ S2P_Cfg3_HW_Ver_Byte1_07 : 0|8@1+ (1,0) [0|255] ""  PC
 SG_ S2P_Cfg3_HW_Ver_Byte2_07 : 8|8@1+ (1,0) [0|255] ""  PC
 SG_ S2P_Cfg3_HW_Ver_Byte3_07 : 16|8@1+ (1,0) [0|255] ""  PC
 SG_ S2P_Cfg3_HW_Ver_Byte4_07 : 24|8@1+ (1,0) [0|255] ""  PC
 SG_ S2P_Cfg3_HW_Ver_Byte5_07 : 32|8@1+ (1,0) [0|255] ""  PC
 SG_ S2P_Cfg3_HW_Ver_Byte6_07 : 40|8@1+ (1,0) [0|255] ""  PC
 SG_ S2P_Cfg3_HW_Ver_Byte7_07 : 48|8@1+ (1,0) [0|255] ""  PC
 SG_ S2P_Cfg3_HW_Ver_Byte8_07 : 56|8@1+ (1,0) [0|255] ""  PC

BO_ 2416242248 S2P_Cfg3__08: 8 SBMU
 SG_ S2P_Cfg3_HW_Ver_Byte1_08 : 0|8@1+ (1,0) [0|255] ""  PC
 SG_ S2P_Cfg3_HW_Ver_Byte2_08 : 8|8@1+ (1,0) [0|255] ""  PC
 SG_ S2P_Cfg3_HW_Ver_Byte3_08 : 16|8@1+ (1,0) [0|255] ""  PC
 SG_ S2P_Cfg3_HW_Ver_Byte4_08 : 24|8@1+ (1,0) [0|255] ""  PC
 SG_ S2P_Cfg3_HW_Ver_Byte5_08 : 32|8@1+ (1,0) [0|255] ""  PC
 SG_ S2P_Cfg3_HW_Ver_Byte6_08 : 40|8@1+ (1,0) [0|255] ""  PC
 SG_ S2P_Cfg3_HW_Ver_Byte7_08 : 48|8@1+ (1,0) [0|255] ""  PC
 SG_ S2P_Cfg3_HW_Ver_Byte8_08 : 56|8@1+ (1,0) [0|255] ""  PC

BO_ 2416242249 S2P_Cfg3__09: 8 SBMU
 SG_ S2P_Cfg3_HW_Ver_Byte1_09 : 0|8@1+ (1,0) [0|255] ""  PC
 SG_ S2P_Cfg3_HW_Ver_Byte2_09 : 8|8@1+ (1,0) [0|255] ""  PC
 SG_ S2P_Cfg3_HW_Ver_Byte3_09 : 16|8@1+ (1,0) [0|255] ""  PC
 SG_ S2P_Cfg3_HW_Ver_Byte4_09 : 24|8@1+ (1,0) [0|255] ""  PC
 SG_ S2P_Cfg3_HW_Ver_Byte5_09 : 32|8@1+ (1,0) [0|255] ""  PC
 SG_ S2P_Cfg3_HW_Ver_Byte6_09 : 40|8@1+ (1,0) [0|255] ""  PC
 SG_ S2P_Cfg3_HW_Ver_Byte7_09 : 48|8@1+ (1,0) [0|255] ""  PC
 SG_ S2P_Cfg3_HW_Ver_Byte8_09 : 56|8@1+ (1,0) [0|255] ""  PC

BO_ 2416242250 S2P_Cfg3__10: 8 SBMU
 SG_ S2P_Cfg3_HW_Ver_Byte1_10 : 0|8@1+ (1,0) [0|255] ""  PC
 SG_ S2P_Cfg3_HW_Ver_Byte2_10 : 8|8@1+ (1,0) [0|255] ""  PC
 SG_ S2P_Cfg3_HW_Ver_Byte3_10 : 16|8@1+ (1,0) [0|255] ""  PC
 SG_ S2P_Cfg3_HW_Ver_Byte4_10 : 24|8@1+ (1,0) [0|255] ""  PC
 SG_ S2P_Cfg3_HW_Ver_Byte5_10 : 32|8@1+ (1,0) [0|255] ""  PC
 SG_ S2P_Cfg3_HW_Ver_Byte6_10 : 40|8@1+ (1,0) [0|255] ""  PC
 SG_ S2P_Cfg3_HW_Ver_Byte7_10 : 48|8@1+ (1,0) [0|255] ""  PC
 SG_ S2P_Cfg3_HW_Ver_Byte8_10 : 56|8@1+ (1,0) [0|255] ""  PC

BO_ 2416242251 S2P_Cfg3__11: 8 SBMU
 SG_ S2P_Cfg3_HW_Ver_Byte1_11 : 0|8@1+ (1,0) [0|255] ""  PC
 SG_ S2P_Cfg3_HW_Ver_Byte2_11 : 8|8@1+ (1,0) [0|255] ""  PC
 SG_ S2P_Cfg3_HW_Ver_Byte3_11 : 16|8@1+ (1,0) [0|255] ""  PC
 SG_ S2P_Cfg3_HW_Ver_Byte4_11 : 24|8@1+ (1,0) [0|255] ""  PC
 SG_ S2P_Cfg3_HW_Ver_Byte5_11 : 32|8@1+ (1,0) [0|255] ""  PC
 SG_ S2P_Cfg3_HW_Ver_Byte6_11 : 40|8@1+ (1,0) [0|255] ""  PC
 SG_ S2P_Cfg3_HW_Ver_Byte7_11 : 48|8@1+ (1,0) [0|255] ""  PC
 SG_ S2P_Cfg3_HW_Ver_Byte8_11 : 56|8@1+ (1,0) [0|255] ""  PC

BO_ 2416242252 S2P_Cfg3__12: 8 SBMU
 SG_ S2P_Cfg3_HW_Ver_Byte1_12 : 0|8@1+ (1,0) [0|255] ""  PC
 SG_ S2P_Cfg3_HW_Ver_Byte2_12 : 8|8@1+ (1,0) [0|255] ""  PC
 SG_ S2P_Cfg3_HW_Ver_Byte3_12 : 16|8@1+ (1,0) [0|255] ""  PC
 SG_ S2P_Cfg3_HW_Ver_Byte4_12 : 24|8@1+ (1,0) [0|255] ""  PC
 SG_ S2P_Cfg3_HW_Ver_Byte5_12 : 32|8@1+ (1,0) [0|255] ""  PC
 SG_ S2P_Cfg3_HW_Ver_Byte6_12 : 40|8@1+ (1,0) [0|255] ""  PC
 SG_ S2P_Cfg3_HW_Ver_Byte7_12 : 48|8@1+ (1,0) [0|255] ""  PC
 SG_ S2P_Cfg3_HW_Ver_Byte8_12 : 56|8@1+ (1,0) [0|255] ""  PC

BO_ 2416242253 S2P_Cfg3__13: 8 SBMU
 SG_ S2P_Cfg3_HW_Ver_Byte1_13 : 0|8@1+ (1,0) [0|255] ""  PC
 SG_ S2P_Cfg3_HW_Ver_Byte2_13 : 8|8@1+ (1,0) [0|255] ""  PC
 SG_ S2P_Cfg3_HW_Ver_Byte3_13 : 16|8@1+ (1,0) [0|255] ""  PC
 SG_ S2P_Cfg3_HW_Ver_Byte4_13 : 24|8@1+ (1,0) [0|255] ""  PC
 SG_ S2P_Cfg3_HW_Ver_Byte5_13 : 32|8@1+ (1,0) [0|255] ""  PC
 SG_ S2P_Cfg3_HW_Ver_Byte6_13 : 40|8@1+ (1,0) [0|255] ""  PC
 SG_ S2P_Cfg3_HW_Ver_Byte7_13 : 48|8@1+ (1,0) [0|255] ""  PC
 SG_ S2P_Cfg3_HW_Ver_Byte8_13 : 56|8@1+ (1,0) [0|255] ""  PC

BO_ 2416242254 S2P_Cfg3__14: 8 SBMU
 SG_ S2P_Cfg3_HW_Ver_Byte1_14 : 0|8@1+ (1,0) [0|255] ""  PC
 SG_ S2P_Cfg3_HW_Ver_Byte2_14 : 8|8@1+ (1,0) [0|255] ""  PC
 SG_ S2P_Cfg3_HW_Ver_Byte3_14 : 16|8@1+ (1,0) [0|255] ""  PC
 SG_ S2P_Cfg3_HW_Ver_Byte4_14 : 24|8@1+ (1,0) [0|255] ""  PC
 SG_ S2P_Cfg3_HW_Ver_Byte5_14 : 32|8@1+ (1,0) [0|255] ""  PC
 SG_ S2P_Cfg3_HW_Ver_Byte6_14 : 40|8@1+ (1,0) [0|255] ""  PC
 SG_ S2P_Cfg3_HW_Ver_Byte7_14 : 48|8@1+ (1,0) [0|255] ""  PC
 SG_ S2P_Cfg3_HW_Ver_Byte8_14 : 56|8@1+ (1,0) [0|255] ""  PC

BO_ 2416242255 S2P_Cfg3__15: 8 SBMU
 SG_ S2P_Cfg3_HW_Ver_Byte1_15 : 0|8@1+ (1,0) [0|255] ""  PC
 SG_ S2P_Cfg3_HW_Ver_Byte2_15 : 8|8@1+ (1,0) [0|255] ""  PC
 SG_ S2P_Cfg3_HW_Ver_Byte3_15 : 16|8@1+ (1,0) [0|255] ""  PC
 SG_ S2P_Cfg3_HW_Ver_Byte4_15 : 24|8@1+ (1,0) [0|255] ""  PC
 SG_ S2P_Cfg3_HW_Ver_Byte5_15 : 32|8@1+ (1,0) [0|255] ""  PC
 SG_ S2P_Cfg3_HW_Ver_Byte6_15 : 40|8@1+ (1,0) [0|255] ""  PC
 SG_ S2P_Cfg3_HW_Ver_Byte7_15 : 48|8@1+ (1,0) [0|255] ""  PC
 SG_ S2P_Cfg3_HW_Ver_Byte8_15 : 56|8@1+ (1,0) [0|255] ""  PC

BO_ 2416242256 S2P_Cfg3__16: 8 SBMU
 SG_ S2P_Cfg3_HW_Ver_Byte1_16 : 0|8@1+ (1,0) [0|255] ""  PC
 SG_ S2P_Cfg3_HW_Ver_Byte2_16 : 8|8@1+ (1,0) [0|255] ""  PC
 SG_ S2P_Cfg3_HW_Ver_Byte3_16 : 16|8@1+ (1,0) [0|255] ""  PC
 SG_ S2P_Cfg3_HW_Ver_Byte4_16 : 24|8@1+ (1,0) [0|255] ""  PC
 SG_ S2P_Cfg3_HW_Ver_Byte5_16 : 32|8@1+ (1,0) [0|255] ""  PC
 SG_ S2P_Cfg3_HW_Ver_Byte6_16 : 40|8@1+ (1,0) [0|255] ""  PC
 SG_ S2P_Cfg3_HW_Ver_Byte7_16 : 48|8@1+ (1,0) [0|255] ""  PC
 SG_ S2P_Cfg3_HW_Ver_Byte8_16 : 56|8@1+ (1,0) [0|255] ""  PC

BO_ 2416242257 S2P_Cfg3__17: 8 SBMU
 SG_ S2P_Cfg3_HW_Ver_Byte1_17 : 0|8@1+ (1,0) [0|255] ""  PC
 SG_ S2P_Cfg3_HW_Ver_Byte2_17 : 8|8@1+ (1,0) [0|255] ""  PC
 SG_ S2P_Cfg3_HW_Ver_Byte3_17 : 16|8@1+ (1,0) [0|255] ""  PC
 SG_ S2P_Cfg3_HW_Ver_Byte4_17 : 24|8@1+ (1,0) [0|255] ""  PC
 SG_ S2P_Cfg3_HW_Ver_Byte5_17 : 32|8@1+ (1,0) [0|255] ""  PC
 SG_ S2P_Cfg3_HW_Ver_Byte6_17 : 40|8@1+ (1,0) [0|255] ""  PC
 SG_ S2P_Cfg3_HW_Ver_Byte7_17 : 48|8@1+ (1,0) [0|255] ""  PC
 SG_ S2P_Cfg3_HW_Ver_Byte8_17 : 56|8@1+ (1,0) [0|255] ""  PC

BO_ 2416242258 S2P_Cfg3__18: 8 SBMU
 SG_ S2P_Cfg3_HW_Ver_Byte1_18 : 0|8@1+ (1,0) [0|255] ""  PC
 SG_ S2P_Cfg3_HW_Ver_Byte2_18 : 8|8@1+ (1,0) [0|255] ""  PC
 SG_ S2P_Cfg3_HW_Ver_Byte3_18 : 16|8@1+ (1,0) [0|255] ""  PC
 SG_ S2P_Cfg3_HW_Ver_Byte4_18 : 24|8@1+ (1,0) [0|255] ""  PC
 SG_ S2P_Cfg3_HW_Ver_Byte5_18 : 32|8@1+ (1,0) [0|255] ""  PC
 SG_ S2P_Cfg3_HW_Ver_Byte6_18 : 40|8@1+ (1,0) [0|255] ""  PC
 SG_ S2P_Cfg3_HW_Ver_Byte7_18 : 48|8@1+ (1,0) [0|255] ""  PC
 SG_ S2P_Cfg3_HW_Ver_Byte8_18 : 56|8@1+ (1,0) [0|255] ""  PC

BO_ 2416242259 S2P_Cfg3__19: 8 SBMU
 SG_ S2P_Cfg3_HW_Ver_Byte1_19 : 0|8@1+ (1,0) [0|255] ""  PC
 SG_ S2P_Cfg3_HW_Ver_Byte2_19 : 8|8@1+ (1,0) [0|255] ""  PC
 SG_ S2P_Cfg3_HW_Ver_Byte3_19 : 16|8@1+ (1,0) [0|255] ""  PC
 SG_ S2P_Cfg3_HW_Ver_Byte4_19 : 24|8@1+ (1,0) [0|255] ""  PC
 SG_ S2P_Cfg3_HW_Ver_Byte5_19 : 32|8@1+ (1,0) [0|255] ""  PC
 SG_ S2P_Cfg3_HW_Ver_Byte6_19 : 40|8@1+ (1,0) [0|255] ""  PC
 SG_ S2P_Cfg3_HW_Ver_Byte7_19 : 48|8@1+ (1,0) [0|255] ""  PC
 SG_ S2P_Cfg3_HW_Ver_Byte8_19 : 56|8@1+ (1,0) [0|255] ""  PC

BO_ 2416242260 S2P_Cfg3__20: 8 SBMU
 SG_ S2P_Cfg3_HW_Ver_Byte1_20 : 0|8@1+ (1,0) [0|255] ""  PC
 SG_ S2P_Cfg3_HW_Ver_Byte2_20 : 8|8@1+ (1,0) [0|255] ""  PC
 SG_ S2P_Cfg3_HW_Ver_Byte3_20 : 16|8@1+ (1,0) [0|255] ""  PC
 SG_ S2P_Cfg3_HW_Ver_Byte4_20 : 24|8@1+ (1,0) [0|255] ""  PC
 SG_ S2P_Cfg3_HW_Ver_Byte5_20 : 32|8@1+ (1,0) [0|255] ""  PC
 SG_ S2P_Cfg3_HW_Ver_Byte6_20 : 40|8@1+ (1,0) [0|255] ""  PC
 SG_ S2P_Cfg3_HW_Ver_Byte7_20 : 48|8@1+ (1,0) [0|255] ""  PC
 SG_ S2P_Cfg3_HW_Ver_Byte8_20 : 56|8@1+ (1,0) [0|255] ""  PC

BO_ 2416242261 S2P_Cfg3__21: 8 SBMU
 SG_ S2P_Cfg3_HW_Ver_Byte1_21 : 0|8@1+ (1,0) [0|255] ""  PC
 SG_ S2P_Cfg3_HW_Ver_Byte2_21 : 8|8@1+ (1,0) [0|255] ""  PC
 SG_ S2P_Cfg3_HW_Ver_Byte3_21 : 16|8@1+ (1,0) [0|255] ""  PC
 SG_ S2P_Cfg3_HW_Ver_Byte4_21 : 24|8@1+ (1,0) [0|255] ""  PC
 SG_ S2P_Cfg3_HW_Ver_Byte5_21 : 32|8@1+ (1,0) [0|255] ""  PC
 SG_ S2P_Cfg3_HW_Ver_Byte6_21 : 40|8@1+ (1,0) [0|255] ""  PC
 SG_ S2P_Cfg3_HW_Ver_Byte7_21 : 48|8@1+ (1,0) [0|255] ""  PC
 SG_ S2P_Cfg3_HW_Ver_Byte8_21 : 56|8@1+ (1,0) [0|255] ""  PC

BO_ 2416242262 S2P_Cfg3__22: 8 SBMU
 SG_ S2P_Cfg3_HW_Ver_Byte1_22 : 0|8@1+ (1,0) [0|255] ""  PC
 SG_ S2P_Cfg3_HW_Ver_Byte2_22 : 8|8@1+ (1,0) [0|255] ""  PC
 SG_ S2P_Cfg3_HW_Ver_Byte3_22 : 16|8@1+ (1,0) [0|255] ""  PC
 SG_ S2P_Cfg3_HW_Ver_Byte4_22 : 24|8@1+ (1,0) [0|255] ""  PC
 SG_ S2P_Cfg3_HW_Ver_Byte5_22 : 32|8@1+ (1,0) [0|255] ""  PC
 SG_ S2P_Cfg3_HW_Ver_Byte6_22 : 40|8@1+ (1,0) [0|255] ""  PC
 SG_ S2P_Cfg3_HW_Ver_Byte7_22 : 48|8@1+ (1,0) [0|255] ""  PC
 SG_ S2P_Cfg3_HW_Ver_Byte8_22 : 56|8@1+ (1,0) [0|255] ""  PC

BO_ 2416242263 S2P_Cfg3__23: 8 SBMU
 SG_ S2P_Cfg3_HW_Ver_Byte1_23 : 0|8@1+ (1,0) [0|255] ""  PC
 SG_ S2P_Cfg3_HW_Ver_Byte2_23 : 8|8@1+ (1,0) [0|255] ""  PC
 SG_ S2P_Cfg3_HW_Ver_Byte3_23 : 16|8@1+ (1,0) [0|255] ""  PC
 SG_ S2P_Cfg3_HW_Ver_Byte4_23 : 24|8@1+ (1,0) [0|255] ""  PC
 SG_ S2P_Cfg3_HW_Ver_Byte5_23 : 32|8@1+ (1,0) [0|255] ""  PC
 SG_ S2P_Cfg3_HW_Ver_Byte6_23 : 40|8@1+ (1,0) [0|255] ""  PC
 SG_ S2P_Cfg3_HW_Ver_Byte7_23 : 48|8@1+ (1,0) [0|255] ""  PC
 SG_ S2P_Cfg3_HW_Ver_Byte8_23 : 56|8@1+ (1,0) [0|255] ""  PC

BO_ 2416242264 S2P_Cfg3__24: 8 SBMU
 SG_ S2P_Cfg3_HW_Ver_Byte1_24 : 0|8@1+ (1,0) [0|255] ""  PC
 SG_ S2P_Cfg3_HW_Ver_Byte2_24 : 8|8@1+ (1,0) [0|255] ""  PC
 SG_ S2P_Cfg3_HW_Ver_Byte3_24 : 16|8@1+ (1,0) [0|255] ""  PC
 SG_ S2P_Cfg3_HW_Ver_Byte4_24 : 24|8@1+ (1,0) [0|255] ""  PC
 SG_ S2P_Cfg3_HW_Ver_Byte5_24 : 32|8@1+ (1,0) [0|255] ""  PC
 SG_ S2P_Cfg3_HW_Ver_Byte6_24 : 40|8@1+ (1,0) [0|255] ""  PC
 SG_ S2P_Cfg3_HW_Ver_Byte7_24 : 48|8@1+ (1,0) [0|255] ""  PC
 SG_ S2P_Cfg3_HW_Ver_Byte8_24 : 56|8@1+ (1,0) [0|255] ""  PC

BO_ 2416242265 S2P_Cfg3__25: 8 SBMU
 SG_ S2P_Cfg3_HW_Ver_Byte1_25 : 0|8@1+ (1,0) [0|255] ""  PC
 SG_ S2P_Cfg3_HW_Ver_Byte2_25 : 8|8@1+ (1,0) [0|255] ""  PC
 SG_ S2P_Cfg3_HW_Ver_Byte3_25 : 16|8@1+ (1,0) [0|255] ""  PC
 SG_ S2P_Cfg3_HW_Ver_Byte4_25 : 24|8@1+ (1,0) [0|255] ""  PC
 SG_ S2P_Cfg3_HW_Ver_Byte5_25 : 32|8@1+ (1,0) [0|255] ""  PC
 SG_ S2P_Cfg3_HW_Ver_Byte6_25 : 40|8@1+ (1,0) [0|255] ""  PC
 SG_ S2P_Cfg3_HW_Ver_Byte7_25 : 48|8@1+ (1,0) [0|255] ""  PC
 SG_ S2P_Cfg3_HW_Ver_Byte8_25 : 56|8@1+ (1,0) [0|255] ""  PC

BO_ 2416242266 S2P_Cfg3__26: 8 SBMU
 SG_ S2P_Cfg3_HW_Ver_Byte1_26 : 0|8@1+ (1,0) [0|255] ""  PC
 SG_ S2P_Cfg3_HW_Ver_Byte2_26 : 8|8@1+ (1,0) [0|255] ""  PC
 SG_ S2P_Cfg3_HW_Ver_Byte3_26 : 16|8@1+ (1,0) [0|255] ""  PC
 SG_ S2P_Cfg3_HW_Ver_Byte4_26 : 24|8@1+ (1,0) [0|255] ""  PC
 SG_ S2P_Cfg3_HW_Ver_Byte5_26 : 32|8@1+ (1,0) [0|255] ""  PC
 SG_ S2P_Cfg3_HW_Ver_Byte6_26 : 40|8@1+ (1,0) [0|255] ""  PC
 SG_ S2P_Cfg3_HW_Ver_Byte7_26 : 48|8@1+ (1,0) [0|255] ""  PC
 SG_ S2P_Cfg3_HW_Ver_Byte8_26 : 56|8@1+ (1,0) [0|255] ""  PC

BO_ 2416242267 S2P_Cfg3__27: 8 SBMU
 SG_ S2P_Cfg3_HW_Ver_Byte1_27 : 0|8@1+ (1,0) [0|255] ""  PC
 SG_ S2P_Cfg3_HW_Ver_Byte2_27 : 8|8@1+ (1,0) [0|255] ""  PC
 SG_ S2P_Cfg3_HW_Ver_Byte3_27 : 16|8@1+ (1,0) [0|255] ""  PC
 SG_ S2P_Cfg3_HW_Ver_Byte4_27 : 24|8@1+ (1,0) [0|255] ""  PC
 SG_ S2P_Cfg3_HW_Ver_Byte5_27 : 32|8@1+ (1,0) [0|255] ""  PC
 SG_ S2P_Cfg3_HW_Ver_Byte6_27 : 40|8@1+ (1,0) [0|255] ""  PC
 SG_ S2P_Cfg3_HW_Ver_Byte7_27 : 48|8@1+ (1,0) [0|255] ""  PC
 SG_ S2P_Cfg3_HW_Ver_Byte8_27 : 56|8@1+ (1,0) [0|255] ""  PC

BO_ 2416242268 S2P_Cfg3__28: 8 SBMU
 SG_ S2P_Cfg3_HW_Ver_Byte1_28 : 0|8@1+ (1,0) [0|255] ""  PC
 SG_ S2P_Cfg3_HW_Ver_Byte2_28 : 8|8@1+ (1,0) [0|255] ""  PC
 SG_ S2P_Cfg3_HW_Ver_Byte3_28 : 16|8@1+ (1,0) [0|255] ""  PC
 SG_ S2P_Cfg3_HW_Ver_Byte4_28 : 24|8@1+ (1,0) [0|255] ""  PC
 SG_ S2P_Cfg3_HW_Ver_Byte5_28 : 32|8@1+ (1,0) [0|255] ""  PC
 SG_ S2P_Cfg3_HW_Ver_Byte6_28 : 40|8@1+ (1,0) [0|255] ""  PC
 SG_ S2P_Cfg3_HW_Ver_Byte7_28 : 48|8@1+ (1,0) [0|255] ""  PC
 SG_ S2P_Cfg3_HW_Ver_Byte8_28 : 56|8@1+ (1,0) [0|255] ""  PC

BO_ 2416242269 S2P_Cfg3__29: 8 SBMU
 SG_ S2P_Cfg3_HW_Ver_Byte1_29 : 0|8@1+ (1,0) [0|255] ""  PC
 SG_ S2P_Cfg3_HW_Ver_Byte2_29 : 8|8@1+ (1,0) [0|255] ""  PC
 SG_ S2P_Cfg3_HW_Ver_Byte3_29 : 16|8@1+ (1,0) [0|255] ""  PC
 SG_ S2P_Cfg3_HW_Ver_Byte4_29 : 24|8@1+ (1,0) [0|255] ""  PC
 SG_ S2P_Cfg3_HW_Ver_Byte5_29 : 32|8@1+ (1,0) [0|255] ""  PC
 SG_ S2P_Cfg3_HW_Ver_Byte6_29 : 40|8@1+ (1,0) [0|255] ""  PC
 SG_ S2P_Cfg3_HW_Ver_Byte7_29 : 48|8@1+ (1,0) [0|255] ""  PC
 SG_ S2P_Cfg3_HW_Ver_Byte8_29 : 56|8@1+ (1,0) [0|255] ""  PC

BO_ 2416242270 S2P_Cfg3__30: 8 SBMU
 SG_ S2P_Cfg3_HW_Ver_Byte1_30 : 0|8@1+ (1,0) [0|255] ""  PC
 SG_ S2P_Cfg3_HW_Ver_Byte2_30 : 8|8@1+ (1,0) [0|255] ""  PC
 SG_ S2P_Cfg3_HW_Ver_Byte3_30 : 16|8@1+ (1,0) [0|255] ""  PC
 SG_ S2P_Cfg3_HW_Ver_Byte4_30 : 24|8@1+ (1,0) [0|255] ""  PC
 SG_ S2P_Cfg3_HW_Ver_Byte5_30 : 32|8@1+ (1,0) [0|255] ""  PC
 SG_ S2P_Cfg3_HW_Ver_Byte6_30 : 40|8@1+ (1,0) [0|255] ""  PC
 SG_ S2P_Cfg3_HW_Ver_Byte7_30 : 48|8@1+ (1,0) [0|255] ""  PC
 SG_ S2P_Cfg3_HW_Ver_Byte8_30 : 56|8@1+ (1,0) [0|255] ""  PC

BO_ 2416242271 S2P_Cfg3__31: 8 SBMU
 SG_ S2P_Cfg3_HW_Ver_Byte1_31 : 0|8@1+ (1,0) [0|255] ""  PC
 SG_ S2P_Cfg3_HW_Ver_Byte2_31 : 8|8@1+ (1,0) [0|255] ""  PC
 SG_ S2P_Cfg3_HW_Ver_Byte3_31 : 16|8@1+ (1,0) [0|255] ""  PC
 SG_ S2P_Cfg3_HW_Ver_Byte4_31 : 24|8@1+ (1,0) [0|255] ""  PC
 SG_ S2P_Cfg3_HW_Ver_Byte5_31 : 32|8@1+ (1,0) [0|255] ""  PC
 SG_ S2P_Cfg3_HW_Ver_Byte6_31 : 40|8@1+ (1,0) [0|255] ""  PC
 SG_ S2P_Cfg3_HW_Ver_Byte7_31 : 48|8@1+ (1,0) [0|255] ""  PC
 SG_ S2P_Cfg3_HW_Ver_Byte8_31 : 56|8@1+ (1,0) [0|255] ""  PC

BO_ 2416242272 S2P_Cfg3__32: 8 SBMU
 SG_ S2P_Cfg3_HW_Ver_Byte1_32 : 0|8@1+ (1,0) [0|255] ""  PC
 SG_ S2P_Cfg3_HW_Ver_Byte2_32 : 8|8@1+ (1,0) [0|255] ""  PC
 SG_ S2P_Cfg3_HW_Ver_Byte3_32 : 16|8@1+ (1,0) [0|255] ""  PC
 SG_ S2P_Cfg3_HW_Ver_Byte4_32 : 24|8@1+ (1,0) [0|255] ""  PC
 SG_ S2P_Cfg3_HW_Ver_Byte5_32 : 32|8@1+ (1,0) [0|255] ""  PC
 SG_ S2P_Cfg3_HW_Ver_Byte6_32 : 40|8@1+ (1,0) [0|255] ""  PC
 SG_ S2P_Cfg3_HW_Ver_Byte7_32 : 48|8@1+ (1,0) [0|255] ""  PC
 SG_ S2P_Cfg3_HW_Ver_Byte8_32 : 56|8@1+ (1,0) [0|255] ""  PC

BO_ 2416242273 S2P_Cfg3__33: 8 SBMU
 SG_ S2P_Cfg3_HW_Ver_Byte1_33 : 0|8@1+ (1,0) [0|255] ""  PC
 SG_ S2P_Cfg3_HW_Ver_Byte2_33 : 8|8@1+ (1,0) [0|255] ""  PC
 SG_ S2P_Cfg3_HW_Ver_Byte3_33 : 16|8@1+ (1,0) [0|255] ""  PC
 SG_ S2P_Cfg3_HW_Ver_Byte4_33 : 24|8@1+ (1,0) [0|255] ""  PC
 SG_ S2P_Cfg3_HW_Ver_Byte5_33 : 32|8@1+ (1,0) [0|255] ""  PC
 SG_ S2P_Cfg3_HW_Ver_Byte6_33 : 40|8@1+ (1,0) [0|255] ""  PC
 SG_ S2P_Cfg3_HW_Ver_Byte7_33 : 48|8@1+ (1,0) [0|255] ""  PC
 SG_ S2P_Cfg3_HW_Ver_Byte8_33 : 56|8@1+ (1,0) [0|255] ""  PC

BO_ 2416242274 S2P_Cfg3__34: 8 SBMU
 SG_ S2P_Cfg3_HW_Ver_Byte1_34 : 0|8@1+ (1,0) [0|255] ""  PC
 SG_ S2P_Cfg3_HW_Ver_Byte2_34 : 8|8@1+ (1,0) [0|255] ""  PC
 SG_ S2P_Cfg3_HW_Ver_Byte3_34 : 16|8@1+ (1,0) [0|255] ""  PC
 SG_ S2P_Cfg3_HW_Ver_Byte4_34 : 24|8@1+ (1,0) [0|255] ""  PC
 SG_ S2P_Cfg3_HW_Ver_Byte5_34 : 32|8@1+ (1,0) [0|255] ""  PC
 SG_ S2P_Cfg3_HW_Ver_Byte6_34 : 40|8@1+ (1,0) [0|255] ""  PC
 SG_ S2P_Cfg3_HW_Ver_Byte7_34 : 48|8@1+ (1,0) [0|255] ""  PC
 SG_ S2P_Cfg3_HW_Ver_Byte8_34 : 56|8@1+ (1,0) [0|255] ""  PC

BO_ 2416242275 S2P_Cfg3__35: 8 SBMU
 SG_ S2P_Cfg3_HW_Ver_Byte1_35 : 0|8@1+ (1,0) [0|255] ""  PC
 SG_ S2P_Cfg3_HW_Ver_Byte2_35 : 8|8@1+ (1,0) [0|255] ""  PC
 SG_ S2P_Cfg3_HW_Ver_Byte3_35 : 16|8@1+ (1,0) [0|255] ""  PC
 SG_ S2P_Cfg3_HW_Ver_Byte4_35 : 24|8@1+ (1,0) [0|255] ""  PC
 SG_ S2P_Cfg3_HW_Ver_Byte5_35 : 32|8@1+ (1,0) [0|255] ""  PC
 SG_ S2P_Cfg3_HW_Ver_Byte6_35 : 40|8@1+ (1,0) [0|255] ""  PC
 SG_ S2P_Cfg3_HW_Ver_Byte7_35 : 48|8@1+ (1,0) [0|255] ""  PC
 SG_ S2P_Cfg3_HW_Ver_Byte8_35 : 56|8@1+ (1,0) [0|255] ""  PC

BO_ 2416242276 S2P_Cfg3__36: 8 SBMU
 SG_ S2P_Cfg3_HW_Ver_Byte1_36 : 0|8@1+ (1,0) [0|255] ""  PC
 SG_ S2P_Cfg3_HW_Ver_Byte2_36 : 8|8@1+ (1,0) [0|255] ""  PC
 SG_ S2P_Cfg3_HW_Ver_Byte3_36 : 16|8@1+ (1,0) [0|255] ""  PC
 SG_ S2P_Cfg3_HW_Ver_Byte4_36 : 24|8@1+ (1,0) [0|255] ""  PC
 SG_ S2P_Cfg3_HW_Ver_Byte5_36 : 32|8@1+ (1,0) [0|255] ""  PC
 SG_ S2P_Cfg3_HW_Ver_Byte6_36 : 40|8@1+ (1,0) [0|255] ""  PC
 SG_ S2P_Cfg3_HW_Ver_Byte7_36 : 48|8@1+ (1,0) [0|255] ""  PC
 SG_ S2P_Cfg3_HW_Ver_Byte8_36 : 56|8@1+ (1,0) [0|255] ""  PC

BO_ 2416242277 S2P_Cfg3__37: 8 SBMU
 SG_ S2P_Cfg3_HW_Ver_Byte1_37 : 0|8@1+ (1,0) [0|255] ""  PC
 SG_ S2P_Cfg3_HW_Ver_Byte2_37 : 8|8@1+ (1,0) [0|255] ""  PC
 SG_ S2P_Cfg3_HW_Ver_Byte3_37 : 16|8@1+ (1,0) [0|255] ""  PC
 SG_ S2P_Cfg3_HW_Ver_Byte4_37 : 24|8@1+ (1,0) [0|255] ""  PC
 SG_ S2P_Cfg3_HW_Ver_Byte5_37 : 32|8@1+ (1,0) [0|255] ""  PC
 SG_ S2P_Cfg3_HW_Ver_Byte6_37 : 40|8@1+ (1,0) [0|255] ""  PC
 SG_ S2P_Cfg3_HW_Ver_Byte7_37 : 48|8@1+ (1,0) [0|255] ""  PC
 SG_ S2P_Cfg3_HW_Ver_Byte8_37 : 56|8@1+ (1,0) [0|255] ""  PC

BO_ 2416242278 S2P_Cfg3__38: 8 SBMU
 SG_ S2P_Cfg3_HW_Ver_Byte1_38 : 0|8@1+ (1,0) [0|255] ""  PC
 SG_ S2P_Cfg3_HW_Ver_Byte2_38 : 8|8@1+ (1,0) [0|255] ""  PC
 SG_ S2P_Cfg3_HW_Ver_Byte3_38 : 16|8@1+ (1,0) [0|255] ""  PC
 SG_ S2P_Cfg3_HW_Ver_Byte4_38 : 24|8@1+ (1,0) [0|255] ""  PC
 SG_ S2P_Cfg3_HW_Ver_Byte5_38 : 32|8@1+ (1,0) [0|255] ""  PC
 SG_ S2P_Cfg3_HW_Ver_Byte6_38 : 40|8@1+ (1,0) [0|255] ""  PC
 SG_ S2P_Cfg3_HW_Ver_Byte7_38 : 48|8@1+ (1,0) [0|255] ""  PC
 SG_ S2P_Cfg3_HW_Ver_Byte8_38 : 56|8@1+ (1,0) [0|255] ""  PC

BO_ 2416242279 S2P_Cfg3__39: 8 SBMU
 SG_ S2P_Cfg3_HW_Ver_Byte1_39 : 0|8@1+ (1,0) [0|255] ""  PC
 SG_ S2P_Cfg3_HW_Ver_Byte2_39 : 8|8@1+ (1,0) [0|255] ""  PC
 SG_ S2P_Cfg3_HW_Ver_Byte3_39 : 16|8@1+ (1,0) [0|255] ""  PC
 SG_ S2P_Cfg3_HW_Ver_Byte4_39 : 24|8@1+ (1,0) [0|255] ""  PC
 SG_ S2P_Cfg3_HW_Ver_Byte5_39 : 32|8@1+ (1,0) [0|255] ""  PC
 SG_ S2P_Cfg3_HW_Ver_Byte6_39 : 40|8@1+ (1,0) [0|255] ""  PC
 SG_ S2P_Cfg3_HW_Ver_Byte7_39 : 48|8@1+ (1,0) [0|255] ""  PC
 SG_ S2P_Cfg3_HW_Ver_Byte8_39 : 56|8@1+ (1,0) [0|255] ""  PC

BO_ 2416242280 S2P_Cfg3__40: 8 SBMU
 SG_ S2P_Cfg3_HW_Ver_Byte1_40 : 0|8@1+ (1,0) [0|255] ""  PC
 SG_ S2P_Cfg3_HW_Ver_Byte2_40 : 8|8@1+ (1,0) [0|255] ""  PC
 SG_ S2P_Cfg3_HW_Ver_Byte3_40 : 16|8@1+ (1,0) [0|255] ""  PC
 SG_ S2P_Cfg3_HW_Ver_Byte4_40 : 24|8@1+ (1,0) [0|255] ""  PC
 SG_ S2P_Cfg3_HW_Ver_Byte5_40 : 32|8@1+ (1,0) [0|255] ""  PC
 SG_ S2P_Cfg3_HW_Ver_Byte6_40 : 40|8@1+ (1,0) [0|255] ""  PC
 SG_ S2P_Cfg3_HW_Ver_Byte7_40 : 48|8@1+ (1,0) [0|255] ""  PC
 SG_ S2P_Cfg3_HW_Ver_Byte8_40 : 56|8@1+ (1,0) [0|255] ""  PC

BO_ 2416242281 S2P_Cfg3__41: 8 SBMU
 SG_ S2P_Cfg3_HW_Ver_Byte1_41 : 0|8@1+ (1,0) [0|255] ""  PC
 SG_ S2P_Cfg3_HW_Ver_Byte2_41 : 8|8@1+ (1,0) [0|255] ""  PC
 SG_ S2P_Cfg3_HW_Ver_Byte3_41 : 16|8@1+ (1,0) [0|255] ""  PC
 SG_ S2P_Cfg3_HW_Ver_Byte4_41 : 24|8@1+ (1,0) [0|255] ""  PC
 SG_ S2P_Cfg3_HW_Ver_Byte5_41 : 32|8@1+ (1,0) [0|255] ""  PC
 SG_ S2P_Cfg3_HW_Ver_Byte6_41 : 40|8@1+ (1,0) [0|255] ""  PC
 SG_ S2P_Cfg3_HW_Ver_Byte7_41 : 48|8@1+ (1,0) [0|255] ""  PC
 SG_ S2P_Cfg3_HW_Ver_Byte8_41 : 56|8@1+ (1,0) [0|255] ""  PC

BO_ 2416242282 S2P_Cfg3__42: 8 SBMU
 SG_ S2P_Cfg3_HW_Ver_Byte1_42 : 0|8@1+ (1,0) [0|255] ""  PC
 SG_ S2P_Cfg3_HW_Ver_Byte2_42 : 8|8@1+ (1,0) [0|255] ""  PC
 SG_ S2P_Cfg3_HW_Ver_Byte3_42 : 16|8@1+ (1,0) [0|255] ""  PC
 SG_ S2P_Cfg3_HW_Ver_Byte4_42 : 24|8@1+ (1,0) [0|255] ""  PC
 SG_ S2P_Cfg3_HW_Ver_Byte5_42 : 32|8@1+ (1,0) [0|255] ""  PC
 SG_ S2P_Cfg3_HW_Ver_Byte6_42 : 40|8@1+ (1,0) [0|255] ""  PC
 SG_ S2P_Cfg3_HW_Ver_Byte7_42 : 48|8@1+ (1,0) [0|255] ""  PC
 SG_ S2P_Cfg3_HW_Ver_Byte8_42 : 56|8@1+ (1,0) [0|255] ""  PC

BO_ 2416242283 S2P_Cfg3__43: 8 SBMU
 SG_ S2P_Cfg3_HW_Ver_Byte1_43 : 0|8@1+ (1,0) [0|255] ""  PC
 SG_ S2P_Cfg3_HW_Ver_Byte2_43 : 8|8@1+ (1,0) [0|255] ""  PC
 SG_ S2P_Cfg3_HW_Ver_Byte3_43 : 16|8@1+ (1,0) [0|255] ""  PC
 SG_ S2P_Cfg3_HW_Ver_Byte4_43 : 24|8@1+ (1,0) [0|255] ""  PC
 SG_ S2P_Cfg3_HW_Ver_Byte5_43 : 32|8@1+ (1,0) [0|255] ""  PC
 SG_ S2P_Cfg3_HW_Ver_Byte6_43 : 40|8@1+ (1,0) [0|255] ""  PC
 SG_ S2P_Cfg3_HW_Ver_Byte7_43 : 48|8@1+ (1,0) [0|255] ""  PC
 SG_ S2P_Cfg3_HW_Ver_Byte8_43 : 56|8@1+ (1,0) [0|255] ""  PC

BO_ 2416242284 S2P_Cfg3__44: 8 SBMU
 SG_ S2P_Cfg3_HW_Ver_Byte1_44 : 0|8@1+ (1,0) [0|255] ""  PC
 SG_ S2P_Cfg3_HW_Ver_Byte2_44 : 8|8@1+ (1,0) [0|255] ""  PC
 SG_ S2P_Cfg3_HW_Ver_Byte3_44 : 16|8@1+ (1,0) [0|255] ""  PC
 SG_ S2P_Cfg3_HW_Ver_Byte4_44 : 24|8@1+ (1,0) [0|255] ""  PC
 SG_ S2P_Cfg3_HW_Ver_Byte5_44 : 32|8@1+ (1,0) [0|255] ""  PC
 SG_ S2P_Cfg3_HW_Ver_Byte6_44 : 40|8@1+ (1,0) [0|255] ""  PC
 SG_ S2P_Cfg3_HW_Ver_Byte7_44 : 48|8@1+ (1,0) [0|255] ""  PC
 SG_ S2P_Cfg3_HW_Ver_Byte8_44 : 56|8@1+ (1,0) [0|255] ""  PC

BO_ 2416242285 S2P_Cfg3__45: 8 SBMU
 SG_ S2P_Cfg3_HW_Ver_Byte1_45 : 0|8@1+ (1,0) [0|255] ""  PC
 SG_ S2P_Cfg3_HW_Ver_Byte2_45 : 8|8@1+ (1,0) [0|255] ""  PC
 SG_ S2P_Cfg3_HW_Ver_Byte3_45 : 16|8@1+ (1,0) [0|255] ""  PC
 SG_ S2P_Cfg3_HW_Ver_Byte4_45 : 24|8@1+ (1,0) [0|255] ""  PC
 SG_ S2P_Cfg3_HW_Ver_Byte5_45 : 32|8@1+ (1,0) [0|255] ""  PC
 SG_ S2P_Cfg3_HW_Ver_Byte6_45 : 40|8@1+ (1,0) [0|255] ""  PC
 SG_ S2P_Cfg3_HW_Ver_Byte7_45 : 48|8@1+ (1,0) [0|255] ""  PC
 SG_ S2P_Cfg3_HW_Ver_Byte8_45 : 56|8@1+ (1,0) [0|255] ""  PC

BO_ 2416242286 S2P_Cfg3__46: 8 SBMU
 SG_ S2P_Cfg3_HW_Ver_Byte1_46 : 0|8@1+ (1,0) [0|255] ""  PC
 SG_ S2P_Cfg3_HW_Ver_Byte2_46 : 8|8@1+ (1,0) [0|255] ""  PC
 SG_ S2P_Cfg3_HW_Ver_Byte3_46 : 16|8@1+ (1,0) [0|255] ""  PC
 SG_ S2P_Cfg3_HW_Ver_Byte4_46 : 24|8@1+ (1,0) [0|255] ""  PC
 SG_ S2P_Cfg3_HW_Ver_Byte5_46 : 32|8@1+ (1,0) [0|255] ""  PC
 SG_ S2P_Cfg3_HW_Ver_Byte6_46 : 40|8@1+ (1,0) [0|255] ""  PC
 SG_ S2P_Cfg3_HW_Ver_Byte7_46 : 48|8@1+ (1,0) [0|255] ""  PC
 SG_ S2P_Cfg3_HW_Ver_Byte8_46 : 56|8@1+ (1,0) [0|255] ""  PC

BO_ 2416242287 S2P_Cfg3__47: 8 SBMU
 SG_ S2P_Cfg3_HW_Ver_Byte1_47 : 0|8@1+ (1,0) [0|255] ""  PC
 SG_ S2P_Cfg3_HW_Ver_Byte2_47 : 8|8@1+ (1,0) [0|255] ""  PC
 SG_ S2P_Cfg3_HW_Ver_Byte3_47 : 16|8@1+ (1,0) [0|255] ""  PC
 SG_ S2P_Cfg3_HW_Ver_Byte4_47 : 24|8@1+ (1,0) [0|255] ""  PC
 SG_ S2P_Cfg3_HW_Ver_Byte5_47 : 32|8@1+ (1,0) [0|255] ""  PC
 SG_ S2P_Cfg3_HW_Ver_Byte6_47 : 40|8@1+ (1,0) [0|255] ""  PC
 SG_ S2P_Cfg3_HW_Ver_Byte7_47 : 48|8@1+ (1,0) [0|255] ""  PC
 SG_ S2P_Cfg3_HW_Ver_Byte8_47 : 56|8@1+ (1,0) [0|255] ""  PC

BO_ 2416242288 S2P_Cfg3__48: 8 SBMU
 SG_ S2P_Cfg3_HW_Ver_Byte1_48 : 0|8@1+ (1,0) [0|255] ""  PC
 SG_ S2P_Cfg3_HW_Ver_Byte2_48 : 8|8@1+ (1,0) [0|255] ""  PC
 SG_ S2P_Cfg3_HW_Ver_Byte3_48 : 16|8@1+ (1,0) [0|255] ""  PC
 SG_ S2P_Cfg3_HW_Ver_Byte4_48 : 24|8@1+ (1,0) [0|255] ""  PC
 SG_ S2P_Cfg3_HW_Ver_Byte5_48 : 32|8@1+ (1,0) [0|255] ""  PC
 SG_ S2P_Cfg3_HW_Ver_Byte6_48 : 40|8@1+ (1,0) [0|255] ""  PC
 SG_ S2P_Cfg3_HW_Ver_Byte7_48 : 48|8@1+ (1,0) [0|255] ""  PC
 SG_ S2P_Cfg3_HW_Ver_Byte8_48 : 56|8@1+ (1,0) [0|255] ""  PC

BO_ 2416242289 S2P_Cfg3__49: 8 SBMU
 SG_ S2P_Cfg3_HW_Ver_Byte1_49 : 0|8@1+ (1,0) [0|255] ""  PC
 SG_ S2P_Cfg3_HW_Ver_Byte2_49 : 8|8@1+ (1,0) [0|255] ""  PC
 SG_ S2P_Cfg3_HW_Ver_Byte3_49 : 16|8@1+ (1,0) [0|255] ""  PC
 SG_ S2P_Cfg3_HW_Ver_Byte4_49 : 24|8@1+ (1,0) [0|255] ""  PC
 SG_ S2P_Cfg3_HW_Ver_Byte5_49 : 32|8@1+ (1,0) [0|255] ""  PC
 SG_ S2P_Cfg3_HW_Ver_Byte6_49 : 40|8@1+ (1,0) [0|255] ""  PC
 SG_ S2P_Cfg3_HW_Ver_Byte7_49 : 48|8@1+ (1,0) [0|255] ""  PC
 SG_ S2P_Cfg3_HW_Ver_Byte8_49 : 56|8@1+ (1,0) [0|255] ""  PC

BO_ 2416242290 S2P_Cfg3__50: 8 SBMU
 SG_ S2P_Cfg3_HW_Ver_Byte1_50 : 0|8@1+ (1,0) [0|255] ""  PC
 SG_ S2P_Cfg3_HW_Ver_Byte2_50 : 8|8@1+ (1,0) [0|255] ""  PC
 SG_ S2P_Cfg3_HW_Ver_Byte3_50 : 16|8@1+ (1,0) [0|255] ""  PC
 SG_ S2P_Cfg3_HW_Ver_Byte4_50 : 24|8@1+ (1,0) [0|255] ""  PC
 SG_ S2P_Cfg3_HW_Ver_Byte5_50 : 32|8@1+ (1,0) [0|255] ""  PC
 SG_ S2P_Cfg3_HW_Ver_Byte6_50 : 40|8@1+ (1,0) [0|255] ""  PC
 SG_ S2P_Cfg3_HW_Ver_Byte7_50 : 48|8@1+ (1,0) [0|255] ""  PC
 SG_ S2P_Cfg3_HW_Ver_Byte8_50 : 56|8@1+ (1,0) [0|255] ""  PC

BO_ 2416242291 S2P_Cfg3__51: 8 SBMU
 SG_ S2P_Cfg3_HW_Ver_Byte1_51 : 0|8@1+ (1,0) [0|255] ""  PC
 SG_ S2P_Cfg3_HW_Ver_Byte2_51 : 8|8@1+ (1,0) [0|255] ""  PC
 SG_ S2P_Cfg3_HW_Ver_Byte3_51 : 16|8@1+ (1,0) [0|255] ""  PC
 SG_ S2P_Cfg3_HW_Ver_Byte4_51 : 24|8@1+ (1,0) [0|255] ""  PC
 SG_ S2P_Cfg3_HW_Ver_Byte5_51 : 32|8@1+ (1,0) [0|255] ""  PC
 SG_ S2P_Cfg3_HW_Ver_Byte6_51 : 40|8@1+ (1,0) [0|255] ""  PC
 SG_ S2P_Cfg3_HW_Ver_Byte7_51 : 48|8@1+ (1,0) [0|255] ""  PC
 SG_ S2P_Cfg3_HW_Ver_Byte8_51 : 56|8@1+ (1,0) [0|255] ""  PC

BO_ 2416242292 S2P_Cfg3__52: 8 SBMU
 SG_ S2P_Cfg3_HW_Ver_Byte1_52 : 0|8@1+ (1,0) [0|255] ""  PC
 SG_ S2P_Cfg3_HW_Ver_Byte2_52 : 8|8@1+ (1,0) [0|255] ""  PC
 SG_ S2P_Cfg3_HW_Ver_Byte3_52 : 16|8@1+ (1,0) [0|255] ""  PC
 SG_ S2P_Cfg3_HW_Ver_Byte4_52 : 24|8@1+ (1,0) [0|255] ""  PC
 SG_ S2P_Cfg3_HW_Ver_Byte5_52 : 32|8@1+ (1,0) [0|255] ""  PC
 SG_ S2P_Cfg3_HW_Ver_Byte6_52 : 40|8@1+ (1,0) [0|255] ""  PC
 SG_ S2P_Cfg3_HW_Ver_Byte7_52 : 48|8@1+ (1,0) [0|255] ""  PC
 SG_ S2P_Cfg3_HW_Ver_Byte8_52 : 56|8@1+ (1,0) [0|255] ""  PC

BO_ 2416242293 S2P_Cfg3__53: 8 SBMU
 SG_ S2P_Cfg3_HW_Ver_Byte1_53 : 0|8@1+ (1,0) [0|255] ""  PC
 SG_ S2P_Cfg3_HW_Ver_Byte2_53 : 8|8@1+ (1,0) [0|255] ""  PC
 SG_ S2P_Cfg3_HW_Ver_Byte3_53 : 16|8@1+ (1,0) [0|255] ""  PC
 SG_ S2P_Cfg3_HW_Ver_Byte4_53 : 24|8@1+ (1,0) [0|255] ""  PC
 SG_ S2P_Cfg3_HW_Ver_Byte5_53 : 32|8@1+ (1,0) [0|255] ""  PC
 SG_ S2P_Cfg3_HW_Ver_Byte6_53 : 40|8@1+ (1,0) [0|255] ""  PC
 SG_ S2P_Cfg3_HW_Ver_Byte7_53 : 48|8@1+ (1,0) [0|255] ""  PC
 SG_ S2P_Cfg3_HW_Ver_Byte8_53 : 56|8@1+ (1,0) [0|255] ""  PC

BO_ 2416242294 S2P_Cfg3__54: 8 SBMU
 SG_ S2P_Cfg3_HW_Ver_Byte1_54 : 0|8@1+ (1,0) [0|255] ""  PC
 SG_ S2P_Cfg3_HW_Ver_Byte2_54 : 8|8@1+ (1,0) [0|255] ""  PC
 SG_ S2P_Cfg3_HW_Ver_Byte3_54 : 16|8@1+ (1,0) [0|255] ""  PC
 SG_ S2P_Cfg3_HW_Ver_Byte4_54 : 24|8@1+ (1,0) [0|255] ""  PC
 SG_ S2P_Cfg3_HW_Ver_Byte5_54 : 32|8@1+ (1,0) [0|255] ""  PC
 SG_ S2P_Cfg3_HW_Ver_Byte6_54 : 40|8@1+ (1,0) [0|255] ""  PC
 SG_ S2P_Cfg3_HW_Ver_Byte7_54 : 48|8@1+ (1,0) [0|255] ""  PC
 SG_ S2P_Cfg3_HW_Ver_Byte8_54 : 56|8@1+ (1,0) [0|255] ""  PC

BO_ 2416242295 S2P_Cfg3__55: 8 SBMU
 SG_ S2P_Cfg3_HW_Ver_Byte1_55 : 0|8@1+ (1,0) [0|255] ""  PC
 SG_ S2P_Cfg3_HW_Ver_Byte2_55 : 8|8@1+ (1,0) [0|255] ""  PC
 SG_ S2P_Cfg3_HW_Ver_Byte3_55 : 16|8@1+ (1,0) [0|255] ""  PC
 SG_ S2P_Cfg3_HW_Ver_Byte4_55 : 24|8@1+ (1,0) [0|255] ""  PC
 SG_ S2P_Cfg3_HW_Ver_Byte5_55 : 32|8@1+ (1,0) [0|255] ""  PC
 SG_ S2P_Cfg3_HW_Ver_Byte6_55 : 40|8@1+ (1,0) [0|255] ""  PC
 SG_ S2P_Cfg3_HW_Ver_Byte7_55 : 48|8@1+ (1,0) [0|255] ""  PC
 SG_ S2P_Cfg3_HW_Ver_Byte8_55 : 56|8@1+ (1,0) [0|255] ""  PC

BO_ 2416242296 S2P_Cfg3__56: 8 SBMU
 SG_ S2P_Cfg3_HW_Ver_Byte1_56 : 0|8@1+ (1,0) [0|255] ""  PC
 SG_ S2P_Cfg3_HW_Ver_Byte2_56 : 8|8@1+ (1,0) [0|255] ""  PC
 SG_ S2P_Cfg3_HW_Ver_Byte3_56 : 16|8@1+ (1,0) [0|255] ""  PC
 SG_ S2P_Cfg3_HW_Ver_Byte4_56 : 24|8@1+ (1,0) [0|255] ""  PC
 SG_ S2P_Cfg3_HW_Ver_Byte5_56 : 32|8@1+ (1,0) [0|255] ""  PC
 SG_ S2P_Cfg3_HW_Ver_Byte6_56 : 40|8@1+ (1,0) [0|255] ""  PC
 SG_ S2P_Cfg3_HW_Ver_Byte7_56 : 48|8@1+ (1,0) [0|255] ""  PC
 SG_ S2P_Cfg3_HW_Ver_Byte8_56 : 56|8@1+ (1,0) [0|255] ""  PC

BO_ 2416242297 S2P_Cfg3__57: 8 SBMU
 SG_ S2P_Cfg3_HW_Ver_Byte1_57 : 0|8@1+ (1,0) [0|255] ""  PC
 SG_ S2P_Cfg3_HW_Ver_Byte2_57 : 8|8@1+ (1,0) [0|255] ""  PC
 SG_ S2P_Cfg3_HW_Ver_Byte3_57 : 16|8@1+ (1,0) [0|255] ""  PC
 SG_ S2P_Cfg3_HW_Ver_Byte4_57 : 24|8@1+ (1,0) [0|255] ""  PC
 SG_ S2P_Cfg3_HW_Ver_Byte5_57 : 32|8@1+ (1,0) [0|255] ""  PC
 SG_ S2P_Cfg3_HW_Ver_Byte6_57 : 40|8@1+ (1,0) [0|255] ""  PC
 SG_ S2P_Cfg3_HW_Ver_Byte7_57 : 48|8@1+ (1,0) [0|255] ""  PC
 SG_ S2P_Cfg3_HW_Ver_Byte8_57 : 56|8@1+ (1,0) [0|255] ""  PC

BO_ 2416242298 S2P_Cfg3__58: 8 SBMU
 SG_ S2P_Cfg3_HW_Ver_Byte1_58 : 0|8@1+ (1,0) [0|255] ""  PC
 SG_ S2P_Cfg3_HW_Ver_Byte2_58 : 8|8@1+ (1,0) [0|255] ""  PC
 SG_ S2P_Cfg3_HW_Ver_Byte3_58 : 16|8@1+ (1,0) [0|255] ""  PC
 SG_ S2P_Cfg3_HW_Ver_Byte4_58 : 24|8@1+ (1,0) [0|255] ""  PC
 SG_ S2P_Cfg3_HW_Ver_Byte5_58 : 32|8@1+ (1,0) [0|255] ""  PC
 SG_ S2P_Cfg3_HW_Ver_Byte6_58 : 40|8@1+ (1,0) [0|255] ""  PC
 SG_ S2P_Cfg3_HW_Ver_Byte7_58 : 48|8@1+ (1,0) [0|255] ""  PC
 SG_ S2P_Cfg3_HW_Ver_Byte8_58 : 56|8@1+ (1,0) [0|255] ""  PC

BO_ 2416242299 S2P_Cfg3__59: 8 SBMU
 SG_ S2P_Cfg3_HW_Ver_Byte1_59 : 0|8@1+ (1,0) [0|255] ""  PC
 SG_ S2P_Cfg3_HW_Ver_Byte2_59 : 8|8@1+ (1,0) [0|255] ""  PC
 SG_ S2P_Cfg3_HW_Ver_Byte3_59 : 16|8@1+ (1,0) [0|255] ""  PC
 SG_ S2P_Cfg3_HW_Ver_Byte4_59 : 24|8@1+ (1,0) [0|255] ""  PC
 SG_ S2P_Cfg3_HW_Ver_Byte5_59 : 32|8@1+ (1,0) [0|255] ""  PC
 SG_ S2P_Cfg3_HW_Ver_Byte6_59 : 40|8@1+ (1,0) [0|255] ""  PC
 SG_ S2P_Cfg3_HW_Ver_Byte7_59 : 48|8@1+ (1,0) [0|255] ""  PC
 SG_ S2P_Cfg3_HW_Ver_Byte8_59 : 56|8@1+ (1,0) [0|255] ""  PC

BO_ 2416242300 S2P_Cfg3__60: 8 SBMU
 SG_ S2P_Cfg3_HW_Ver_Byte1_60 : 0|8@1+ (1,0) [0|255] ""  PC
 SG_ S2P_Cfg3_HW_Ver_Byte2_60 : 8|8@1+ (1,0) [0|255] ""  PC
 SG_ S2P_Cfg3_HW_Ver_Byte3_60 : 16|8@1+ (1,0) [0|255] ""  PC
 SG_ S2P_Cfg3_HW_Ver_Byte4_60 : 24|8@1+ (1,0) [0|255] ""  PC
 SG_ S2P_Cfg3_HW_Ver_Byte5_60 : 32|8@1+ (1,0) [0|255] ""  PC
 SG_ S2P_Cfg3_HW_Ver_Byte6_60 : 40|8@1+ (1,0) [0|255] ""  PC
 SG_ S2P_Cfg3_HW_Ver_Byte7_60 : 48|8@1+ (1,0) [0|255] ""  PC
 SG_ S2P_Cfg3_HW_Ver_Byte8_60 : 56|8@1+ (1,0) [0|255] ""  PC

BO_ 2416242301 S2P_Cfg3__61: 8 SBMU
 SG_ S2P_Cfg3_HW_Ver_Byte1_61 : 0|8@1+ (1,0) [0|255] ""  PC
 SG_ S2P_Cfg3_HW_Ver_Byte2_61 : 8|8@1+ (1,0) [0|255] ""  PC
 SG_ S2P_Cfg3_HW_Ver_Byte3_61 : 16|8@1+ (1,0) [0|255] ""  PC
 SG_ S2P_Cfg3_HW_Ver_Byte4_61 : 24|8@1+ (1,0) [0|255] ""  PC
 SG_ S2P_Cfg3_HW_Ver_Byte5_61 : 32|8@1+ (1,0) [0|255] ""  PC
 SG_ S2P_Cfg3_HW_Ver_Byte6_61 : 40|8@1+ (1,0) [0|255] ""  PC
 SG_ S2P_Cfg3_HW_Ver_Byte7_61 : 48|8@1+ (1,0) [0|255] ""  PC
 SG_ S2P_Cfg3_HW_Ver_Byte8_61 : 56|8@1+ (1,0) [0|255] ""  PC

BO_ 2416242302 S2P_Cfg3__62: 8 SBMU
 SG_ S2P_Cfg3_HW_Ver_Byte1_62 : 0|8@1+ (1,0) [0|255] ""  PC
 SG_ S2P_Cfg3_HW_Ver_Byte2_62 : 8|8@1+ (1,0) [0|255] ""  PC
 SG_ S2P_Cfg3_HW_Ver_Byte3_62 : 16|8@1+ (1,0) [0|255] ""  PC
 SG_ S2P_Cfg3_HW_Ver_Byte4_62 : 24|8@1+ (1,0) [0|255] ""  PC
 SG_ S2P_Cfg3_HW_Ver_Byte5_62 : 32|8@1+ (1,0) [0|255] ""  PC
 SG_ S2P_Cfg3_HW_Ver_Byte6_62 : 40|8@1+ (1,0) [0|255] ""  PC
 SG_ S2P_Cfg3_HW_Ver_Byte7_62 : 48|8@1+ (1,0) [0|255] ""  PC
 SG_ S2P_Cfg3_HW_Ver_Byte8_62 : 56|8@1+ (1,0) [0|255] ""  PC

BO_ 2416242303 S2P_Cfg3__63: 8 SBMU
 SG_ S2P_Cfg3_HW_Ver_Byte1_63 : 0|8@1+ (1,0) [0|255] ""  PC
 SG_ S2P_Cfg3_HW_Ver_Byte2_63 : 8|8@1+ (1,0) [0|255] ""  PC
 SG_ S2P_Cfg3_HW_Ver_Byte3_63 : 16|8@1+ (1,0) [0|255] ""  PC
 SG_ S2P_Cfg3_HW_Ver_Byte4_63 : 24|8@1+ (1,0) [0|255] ""  PC
 SG_ S2P_Cfg3_HW_Ver_Byte5_63 : 32|8@1+ (1,0) [0|255] ""  PC
 SG_ S2P_Cfg3_HW_Ver_Byte6_63 : 40|8@1+ (1,0) [0|255] ""  PC
 SG_ S2P_Cfg3_HW_Ver_Byte7_63 : 48|8@1+ (1,0) [0|255] ""  PC
 SG_ S2P_Cfg3_HW_Ver_Byte8_63 : 56|8@1+ (1,0) [0|255] ""  PC

BO_ 2416307777 S2P_Cfg4__01: 8 SBMU
 SG_ S2P_Cfg4_HW_Ver_Byte9_01 : 0|8@1+ (1,0) [0|255] ""  PC
 SG_ S2P_Cfg4_HW_Ver_Byte10_01 : 8|8@1+ (1,0) [0|255] ""  PC
 SG_ S2P_Cfg4_HW_Ver_Byte11_01 : 16|8@1+ (1,0) [0|255] ""  PC
 SG_ S2P_Cfg4_HW_Ver_Byte12_01 : 24|8@1+ (1,0) [0|255] ""  PC
 SG_ S2P_Cfg4_HW_Ver_Byte13_01 : 32|8@1+ (1,0) [0|255] ""  PC
 SG_ S2P_Cfg4_HW_Ver_Byte14_01 : 40|8@1+ (1,0) [0|255] ""  PC
 SG_ S2P_Cfg4_HW_Ver_Byte15_01 : 48|8@1+ (1,0) [0|255] ""  PC
 SG_ S2P_Cfg4_HW_Ver_Byte16_01 : 56|8@1+ (1,0) [0|255] ""  PC

BO_ 2416307778 S2P_Cfg4__02: 8 SBMU
 SG_ S2P_Cfg4_HW_Ver_Byte9_02 : 0|8@1+ (1,0) [0|255] ""  PC
 SG_ S2P_Cfg4_HW_Ver_Byte10_02 : 8|8@1+ (1,0) [0|255] ""  PC
 SG_ S2P_Cfg4_HW_Ver_Byte11_02 : 16|8@1+ (1,0) [0|255] ""  PC
 SG_ S2P_Cfg4_HW_Ver_Byte12_02 : 24|8@1+ (1,0) [0|255] ""  PC
 SG_ S2P_Cfg4_HW_Ver_Byte13_02 : 32|8@1+ (1,0) [0|255] ""  PC
 SG_ S2P_Cfg4_HW_Ver_Byte14_02 : 40|8@1+ (1,0) [0|255] ""  PC
 SG_ S2P_Cfg4_HW_Ver_Byte15_02 : 48|8@1+ (1,0) [0|255] ""  PC
 SG_ S2P_Cfg4_HW_Ver_Byte16_02 : 56|8@1+ (1,0) [0|255] ""  PC

BO_ 2416307779 S2P_Cfg4__03: 8 SBMU
 SG_ S2P_Cfg4_HW_Ver_Byte9_03 : 0|8@1+ (1,0) [0|255] ""  PC
 SG_ S2P_Cfg4_HW_Ver_Byte10_03 : 8|8@1+ (1,0) [0|255] ""  PC
 SG_ S2P_Cfg4_HW_Ver_Byte11_03 : 16|8@1+ (1,0) [0|255] ""  PC
 SG_ S2P_Cfg4_HW_Ver_Byte12_03 : 24|8@1+ (1,0) [0|255] ""  PC
 SG_ S2P_Cfg4_HW_Ver_Byte13_03 : 32|8@1+ (1,0) [0|255] ""  PC
 SG_ S2P_Cfg4_HW_Ver_Byte14_03 : 40|8@1+ (1,0) [0|255] ""  PC
 SG_ S2P_Cfg4_HW_Ver_Byte15_03 : 48|8@1+ (1,0) [0|255] ""  PC
 SG_ S2P_Cfg4_HW_Ver_Byte16_03 : 56|8@1+ (1,0) [0|255] ""  PC

BO_ 2416307780 S2P_Cfg4__04: 8 SBMU
 SG_ S2P_Cfg4_HW_Ver_Byte9_04 : 0|8@1+ (1,0) [0|255] ""  PC
 SG_ S2P_Cfg4_HW_Ver_Byte10_04 : 8|8@1+ (1,0) [0|255] ""  PC
 SG_ S2P_Cfg4_HW_Ver_Byte11_04 : 16|8@1+ (1,0) [0|255] ""  PC
 SG_ S2P_Cfg4_HW_Ver_Byte12_04 : 24|8@1+ (1,0) [0|255] ""  PC
 SG_ S2P_Cfg4_HW_Ver_Byte13_04 : 32|8@1+ (1,0) [0|255] ""  PC
 SG_ S2P_Cfg4_HW_Ver_Byte14_04 : 40|8@1+ (1,0) [0|255] ""  PC
 SG_ S2P_Cfg4_HW_Ver_Byte15_04 : 48|8@1+ (1,0) [0|255] ""  PC
 SG_ S2P_Cfg4_HW_Ver_Byte16_04 : 56|8@1+ (1,0) [0|255] ""  PC

BO_ 2416307781 S2P_Cfg4__05: 8 SBMU
 SG_ S2P_Cfg4_HW_Ver_Byte9_05 : 0|8@1+ (1,0) [0|255] ""  PC
 SG_ S2P_Cfg4_HW_Ver_Byte10_05 : 8|8@1+ (1,0) [0|255] ""  PC
 SG_ S2P_Cfg4_HW_Ver_Byte11_05 : 16|8@1+ (1,0) [0|255] ""  PC
 SG_ S2P_Cfg4_HW_Ver_Byte12_05 : 24|8@1+ (1,0) [0|255] ""  PC
 SG_ S2P_Cfg4_HW_Ver_Byte13_05 : 32|8@1+ (1,0) [0|255] ""  PC
 SG_ S2P_Cfg4_HW_Ver_Byte14_05 : 40|8@1+ (1,0) [0|255] ""  PC
 SG_ S2P_Cfg4_HW_Ver_Byte15_05 : 48|8@1+ (1,0) [0|255] ""  PC
 SG_ S2P_Cfg4_HW_Ver_Byte16_05 : 56|8@1+ (1,0) [0|255] ""  PC

BO_ 2416307782 S2P_Cfg4__06: 8 SBMU
 SG_ S2P_Cfg4_HW_Ver_Byte9_06 : 0|8@1+ (1,0) [0|255] ""  PC
 SG_ S2P_Cfg4_HW_Ver_Byte10_06 : 8|8@1+ (1,0) [0|255] ""  PC
 SG_ S2P_Cfg4_HW_Ver_Byte11_06 : 16|8@1+ (1,0) [0|255] ""  PC
 SG_ S2P_Cfg4_HW_Ver_Byte12_06 : 24|8@1+ (1,0) [0|255] ""  PC
 SG_ S2P_Cfg4_HW_Ver_Byte13_06 : 32|8@1+ (1,0) [0|255] ""  PC
 SG_ S2P_Cfg4_HW_Ver_Byte14_06 : 40|8@1+ (1,0) [0|255] ""  PC
 SG_ S2P_Cfg4_HW_Ver_Byte15_06 : 48|8@1+ (1,0) [0|255] ""  PC
 SG_ S2P_Cfg4_HW_Ver_Byte16_06 : 56|8@1+ (1,0) [0|255] ""  PC

BO_ 2416307783 S2P_Cfg4__07: 8 SBMU
 SG_ S2P_Cfg4_HW_Ver_Byte9_07 : 0|8@1+ (1,0) [0|255] ""  PC
 SG_ S2P_Cfg4_HW_Ver_Byte10_07 : 8|8@1+ (1,0) [0|255] ""  PC
 SG_ S2P_Cfg4_HW_Ver_Byte11_07 : 16|8@1+ (1,0) [0|255] ""  PC
 SG_ S2P_Cfg4_HW_Ver_Byte12_07 : 24|8@1+ (1,0) [0|255] ""  PC
 SG_ S2P_Cfg4_HW_Ver_Byte13_07 : 32|8@1+ (1,0) [0|255] ""  PC
 SG_ S2P_Cfg4_HW_Ver_Byte14_07 : 40|8@1+ (1,0) [0|255] ""  PC
 SG_ S2P_Cfg4_HW_Ver_Byte15_07 : 48|8@1+ (1,0) [0|255] ""  PC
 SG_ S2P_Cfg4_HW_Ver_Byte16_07 : 56|8@1+ (1,0) [0|255] ""  PC

BO_ 2416307784 S2P_Cfg4__08: 8 SBMU
 SG_ S2P_Cfg4_HW_Ver_Byte9_08 : 0|8@1+ (1,0) [0|255] ""  PC
 SG_ S2P_Cfg4_HW_Ver_Byte10_08 : 8|8@1+ (1,0) [0|255] ""  PC
 SG_ S2P_Cfg4_HW_Ver_Byte11_08 : 16|8@1+ (1,0) [0|255] ""  PC
 SG_ S2P_Cfg4_HW_Ver_Byte12_08 : 24|8@1+ (1,0) [0|255] ""  PC
 SG_ S2P_Cfg4_HW_Ver_Byte13_08 : 32|8@1+ (1,0) [0|255] ""  PC
 SG_ S2P_Cfg4_HW_Ver_Byte14_08 : 40|8@1+ (1,0) [0|255] ""  PC
 SG_ S2P_Cfg4_HW_Ver_Byte15_08 : 48|8@1+ (1,0) [0|255] ""  PC
 SG_ S2P_Cfg4_HW_Ver_Byte16_08 : 56|8@1+ (1,0) [0|255] ""  PC

BO_ 2416307785 S2P_Cfg4__09: 8 SBMU
 SG_ S2P_Cfg4_HW_Ver_Byte9_09 : 0|8@1+ (1,0) [0|255] ""  PC
 SG_ S2P_Cfg4_HW_Ver_Byte10_09 : 8|8@1+ (1,0) [0|255] ""  PC
 SG_ S2P_Cfg4_HW_Ver_Byte11_09 : 16|8@1+ (1,0) [0|255] ""  PC
 SG_ S2P_Cfg4_HW_Ver_Byte12_09 : 24|8@1+ (1,0) [0|255] ""  PC
 SG_ S2P_Cfg4_HW_Ver_Byte13_09 : 32|8@1+ (1,0) [0|255] ""  PC
 SG_ S2P_Cfg4_HW_Ver_Byte14_09 : 40|8@1+ (1,0) [0|255] ""  PC
 SG_ S2P_Cfg4_HW_Ver_Byte15_09 : 48|8@1+ (1,0) [0|255] ""  PC
 SG_ S2P_Cfg4_HW_Ver_Byte16_09 : 56|8@1+ (1,0) [0|255] ""  PC

BO_ 2416307786 S2P_Cfg4__10: 8 SBMU
 SG_ S2P_Cfg4_HW_Ver_Byte9_10 : 0|8@1+ (1,0) [0|255] ""  PC
 SG_ S2P_Cfg4_HW_Ver_Byte10_10 : 8|8@1+ (1,0) [0|255] ""  PC
 SG_ S2P_Cfg4_HW_Ver_Byte11_10 : 16|8@1+ (1,0) [0|255] ""  PC
 SG_ S2P_Cfg4_HW_Ver_Byte12_10 : 24|8@1+ (1,0) [0|255] ""  PC
 SG_ S2P_Cfg4_HW_Ver_Byte13_10 : 32|8@1+ (1,0) [0|255] ""  PC
 SG_ S2P_Cfg4_HW_Ver_Byte14_10 : 40|8@1+ (1,0) [0|255] ""  PC
 SG_ S2P_Cfg4_HW_Ver_Byte15_10 : 48|8@1+ (1,0) [0|255] ""  PC
 SG_ S2P_Cfg4_HW_Ver_Byte16_10 : 56|8@1+ (1,0) [0|255] ""  PC

BO_ 2416307787 S2P_Cfg4__11: 8 SBMU
 SG_ S2P_Cfg4_HW_Ver_Byte9_11 : 0|8@1+ (1,0) [0|255] ""  PC
 SG_ S2P_Cfg4_HW_Ver_Byte10_11 : 8|8@1+ (1,0) [0|255] ""  PC
 SG_ S2P_Cfg4_HW_Ver_Byte11_11 : 16|8@1+ (1,0) [0|255] ""  PC
 SG_ S2P_Cfg4_HW_Ver_Byte12_11 : 24|8@1+ (1,0) [0|255] ""  PC
 SG_ S2P_Cfg4_HW_Ver_Byte13_11 : 32|8@1+ (1,0) [0|255] ""  PC
 SG_ S2P_Cfg4_HW_Ver_Byte14_11 : 40|8@1+ (1,0) [0|255] ""  PC
 SG_ S2P_Cfg4_HW_Ver_Byte15_11 : 48|8@1+ (1,0) [0|255] ""  PC
 SG_ S2P_Cfg4_HW_Ver_Byte16_11 : 56|8@1+ (1,0) [0|255] ""  PC

BO_ 2416307788 S2P_Cfg4__12: 8 SBMU
 SG_ S2P_Cfg4_HW_Ver_Byte9_12 : 0|8@1+ (1,0) [0|255] ""  PC
 SG_ S2P_Cfg4_HW_Ver_Byte10_12 : 8|8@1+ (1,0) [0|255] ""  PC
 SG_ S2P_Cfg4_HW_Ver_Byte11_12 : 16|8@1+ (1,0) [0|255] ""  PC
 SG_ S2P_Cfg4_HW_Ver_Byte12_12 : 24|8@1+ (1,0) [0|255] ""  PC
 SG_ S2P_Cfg4_HW_Ver_Byte13_12 : 32|8@1+ (1,0) [0|255] ""  PC
 SG_ S2P_Cfg4_HW_Ver_Byte14_12 : 40|8@1+ (1,0) [0|255] ""  PC
 SG_ S2P_Cfg4_HW_Ver_Byte15_12 : 48|8@1+ (1,0) [0|255] ""  PC
 SG_ S2P_Cfg4_HW_Ver_Byte16_12 : 56|8@1+ (1,0) [0|255] ""  PC

BO_ 2416307789 S2P_Cfg4__13: 8 SBMU
 SG_ S2P_Cfg4_HW_Ver_Byte9_13 : 0|8@1+ (1,0) [0|255] ""  PC
 SG_ S2P_Cfg4_HW_Ver_Byte10_13 : 8|8@1+ (1,0) [0|255] ""  PC
 SG_ S2P_Cfg4_HW_Ver_Byte11_13 : 16|8@1+ (1,0) [0|255] ""  PC
 SG_ S2P_Cfg4_HW_Ver_Byte12_13 : 24|8@1+ (1,0) [0|255] ""  PC
 SG_ S2P_Cfg4_HW_Ver_Byte13_13 : 32|8@1+ (1,0) [0|255] ""  PC
 SG_ S2P_Cfg4_HW_Ver_Byte14_13 : 40|8@1+ (1,0) [0|255] ""  PC
 SG_ S2P_Cfg4_HW_Ver_Byte15_13 : 48|8@1+ (1,0) [0|255] ""  PC
 SG_ S2P_Cfg4_HW_Ver_Byte16_13 : 56|8@1+ (1,0) [0|255] ""  PC

BO_ 2416307790 S2P_Cfg4__14: 8 SBMU
 SG_ S2P_Cfg4_HW_Ver_Byte9_14 : 0|8@1+ (1,0) [0|255] ""  PC
 SG_ S2P_Cfg4_HW_Ver_Byte10_14 : 8|8@1+ (1,0) [0|255] ""  PC
 SG_ S2P_Cfg4_HW_Ver_Byte11_14 : 16|8@1+ (1,0) [0|255] ""  PC
 SG_ S2P_Cfg4_HW_Ver_Byte12_14 : 24|8@1+ (1,0) [0|255] ""  PC
 SG_ S2P_Cfg4_HW_Ver_Byte13_14 : 32|8@1+ (1,0) [0|255] ""  PC
 SG_ S2P_Cfg4_HW_Ver_Byte14_14 : 40|8@1+ (1,0) [0|255] ""  PC
 SG_ S2P_Cfg4_HW_Ver_Byte15_14 : 48|8@1+ (1,0) [0|255] ""  PC
 SG_ S2P_Cfg4_HW_Ver_Byte16_14 : 56|8@1+ (1,0) [0|255] ""  PC

BO_ 2416307791 S2P_Cfg4__15: 8 SBMU
 SG_ S2P_Cfg4_HW_Ver_Byte9_15 : 0|8@1+ (1,0) [0|255] ""  PC
 SG_ S2P_Cfg4_HW_Ver_Byte10_15 : 8|8@1+ (1,0) [0|255] ""  PC
 SG_ S2P_Cfg4_HW_Ver_Byte11_15 : 16|8@1+ (1,0) [0|255] ""  PC
 SG_ S2P_Cfg4_HW_Ver_Byte12_15 : 24|8@1+ (1,0) [0|255] ""  PC
 SG_ S2P_Cfg4_HW_Ver_Byte13_15 : 32|8@1+ (1,0) [0|255] ""  PC
 SG_ S2P_Cfg4_HW_Ver_Byte14_15 : 40|8@1+ (1,0) [0|255] ""  PC
 SG_ S2P_Cfg4_HW_Ver_Byte15_15 : 48|8@1+ (1,0) [0|255] ""  PC
 SG_ S2P_Cfg4_HW_Ver_Byte16_15 : 56|8@1+ (1,0) [0|255] ""  PC

BO_ 2416307792 S2P_Cfg4__16: 8 SBMU
 SG_ S2P_Cfg4_HW_Ver_Byte9_16 : 0|8@1+ (1,0) [0|255] ""  PC
 SG_ S2P_Cfg4_HW_Ver_Byte10_16 : 8|8@1+ (1,0) [0|255] ""  PC
 SG_ S2P_Cfg4_HW_Ver_Byte11_16 : 16|8@1+ (1,0) [0|255] ""  PC
 SG_ S2P_Cfg4_HW_Ver_Byte12_16 : 24|8@1+ (1,0) [0|255] ""  PC
 SG_ S2P_Cfg4_HW_Ver_Byte13_16 : 32|8@1+ (1,0) [0|255] ""  PC
 SG_ S2P_Cfg4_HW_Ver_Byte14_16 : 40|8@1+ (1,0) [0|255] ""  PC
 SG_ S2P_Cfg4_HW_Ver_Byte15_16 : 48|8@1+ (1,0) [0|255] ""  PC
 SG_ S2P_Cfg4_HW_Ver_Byte16_16 : 56|8@1+ (1,0) [0|255] ""  PC

BO_ 2416307793 S2P_Cfg4__17: 8 SBMU
 SG_ S2P_Cfg4_HW_Ver_Byte9_17 : 0|8@1+ (1,0) [0|255] ""  PC
 SG_ S2P_Cfg4_HW_Ver_Byte10_17 : 8|8@1+ (1,0) [0|255] ""  PC
 SG_ S2P_Cfg4_HW_Ver_Byte11_17 : 16|8@1+ (1,0) [0|255] ""  PC
 SG_ S2P_Cfg4_HW_Ver_Byte12_17 : 24|8@1+ (1,0) [0|255] ""  PC
 SG_ S2P_Cfg4_HW_Ver_Byte13_17 : 32|8@1+ (1,0) [0|255] ""  PC
 SG_ S2P_Cfg4_HW_Ver_Byte14_17 : 40|8@1+ (1,0) [0|255] ""  PC
 SG_ S2P_Cfg4_HW_Ver_Byte15_17 : 48|8@1+ (1,0) [0|255] ""  PC
 SG_ S2P_Cfg4_HW_Ver_Byte16_17 : 56|8@1+ (1,0) [0|255] ""  PC

BO_ 2416307794 S2P_Cfg4__18: 8 SBMU
 SG_ S2P_Cfg4_HW_Ver_Byte9_18 : 0|8@1+ (1,0) [0|255] ""  PC
 SG_ S2P_Cfg4_HW_Ver_Byte10_18 : 8|8@1+ (1,0) [0|255] ""  PC
 SG_ S2P_Cfg4_HW_Ver_Byte11_18 : 16|8@1+ (1,0) [0|255] ""  PC
 SG_ S2P_Cfg4_HW_Ver_Byte12_18 : 24|8@1+ (1,0) [0|255] ""  PC
 SG_ S2P_Cfg4_HW_Ver_Byte13_18 : 32|8@1+ (1,0) [0|255] ""  PC
 SG_ S2P_Cfg4_HW_Ver_Byte14_18 : 40|8@1+ (1,0) [0|255] ""  PC
 SG_ S2P_Cfg4_HW_Ver_Byte15_18 : 48|8@1+ (1,0) [0|255] ""  PC
 SG_ S2P_Cfg4_HW_Ver_Byte16_18 : 56|8@1+ (1,0) [0|255] ""  PC

BO_ 2416307795 S2P_Cfg4__19: 8 SBMU
 SG_ S2P_Cfg4_HW_Ver_Byte9_19 : 0|8@1+ (1,0) [0|255] ""  PC
 SG_ S2P_Cfg4_HW_Ver_Byte10_19 : 8|8@1+ (1,0) [0|255] ""  PC
 SG_ S2P_Cfg4_HW_Ver_Byte11_19 : 16|8@1+ (1,0) [0|255] ""  PC
 SG_ S2P_Cfg4_HW_Ver_Byte12_19 : 24|8@1+ (1,0) [0|255] ""  PC
 SG_ S2P_Cfg4_HW_Ver_Byte13_19 : 32|8@1+ (1,0) [0|255] ""  PC
 SG_ S2P_Cfg4_HW_Ver_Byte14_19 : 40|8@1+ (1,0) [0|255] ""  PC
 SG_ S2P_Cfg4_HW_Ver_Byte15_19 : 48|8@1+ (1,0) [0|255] ""  PC
 SG_ S2P_Cfg4_HW_Ver_Byte16_19 : 56|8@1+ (1,0) [0|255] ""  PC

BO_ 2416307796 S2P_Cfg4__20: 8 SBMU
 SG_ S2P_Cfg4_HW_Ver_Byte9_20 : 0|8@1+ (1,0) [0|255] ""  PC
 SG_ S2P_Cfg4_HW_Ver_Byte10_20 : 8|8@1+ (1,0) [0|255] ""  PC
 SG_ S2P_Cfg4_HW_Ver_Byte11_20 : 16|8@1+ (1,0) [0|255] ""  PC
 SG_ S2P_Cfg4_HW_Ver_Byte12_20 : 24|8@1+ (1,0) [0|255] ""  PC
 SG_ S2P_Cfg4_HW_Ver_Byte13_20 : 32|8@1+ (1,0) [0|255] ""  PC
 SG_ S2P_Cfg4_HW_Ver_Byte14_20 : 40|8@1+ (1,0) [0|255] ""  PC
 SG_ S2P_Cfg4_HW_Ver_Byte15_20 : 48|8@1+ (1,0) [0|255] ""  PC
 SG_ S2P_Cfg4_HW_Ver_Byte16_20 : 56|8@1+ (1,0) [0|255] ""  PC

BO_ 2416307797 S2P_Cfg4__21: 8 SBMU
 SG_ S2P_Cfg4_HW_Ver_Byte9_21 : 0|8@1+ (1,0) [0|255] ""  PC
 SG_ S2P_Cfg4_HW_Ver_Byte10_21 : 8|8@1+ (1,0) [0|255] ""  PC
 SG_ S2P_Cfg4_HW_Ver_Byte11_21 : 16|8@1+ (1,0) [0|255] ""  PC
 SG_ S2P_Cfg4_HW_Ver_Byte12_21 : 24|8@1+ (1,0) [0|255] ""  PC
 SG_ S2P_Cfg4_HW_Ver_Byte13_21 : 32|8@1+ (1,0) [0|255] ""  PC
 SG_ S2P_Cfg4_HW_Ver_Byte14_21 : 40|8@1+ (1,0) [0|255] ""  PC
 SG_ S2P_Cfg4_HW_Ver_Byte15_21 : 48|8@1+ (1,0) [0|255] ""  PC
 SG_ S2P_Cfg4_HW_Ver_Byte16_21 : 56|8@1+ (1,0) [0|255] ""  PC

BO_ 2416307798 S2P_Cfg4__22: 8 SBMU
 SG_ S2P_Cfg4_HW_Ver_Byte9_22 : 0|8@1+ (1,0) [0|255] ""  PC
 SG_ S2P_Cfg4_HW_Ver_Byte10_22 : 8|8@1+ (1,0) [0|255] ""  PC
 SG_ S2P_Cfg4_HW_Ver_Byte11_22 : 16|8@1+ (1,0) [0|255] ""  PC
 SG_ S2P_Cfg4_HW_Ver_Byte12_22 : 24|8@1+ (1,0) [0|255] ""  PC
 SG_ S2P_Cfg4_HW_Ver_Byte13_22 : 32|8@1+ (1,0) [0|255] ""  PC
 SG_ S2P_Cfg4_HW_Ver_Byte14_22 : 40|8@1+ (1,0) [0|255] ""  PC
 SG_ S2P_Cfg4_HW_Ver_Byte15_22 : 48|8@1+ (1,0) [0|255] ""  PC
 SG_ S2P_Cfg4_HW_Ver_Byte16_22 : 56|8@1+ (1,0) [0|255] ""  PC

BO_ 2416307799 S2P_Cfg4__23: 8 SBMU
 SG_ S2P_Cfg4_HW_Ver_Byte9_23 : 0|8@1+ (1,0) [0|255] ""  PC
 SG_ S2P_Cfg4_HW_Ver_Byte10_23 : 8|8@1+ (1,0) [0|255] ""  PC
 SG_ S2P_Cfg4_HW_Ver_Byte11_23 : 16|8@1+ (1,0) [0|255] ""  PC
 SG_ S2P_Cfg4_HW_Ver_Byte12_23 : 24|8@1+ (1,0) [0|255] ""  PC
 SG_ S2P_Cfg4_HW_Ver_Byte13_23 : 32|8@1+ (1,0) [0|255] ""  PC
 SG_ S2P_Cfg4_HW_Ver_Byte14_23 : 40|8@1+ (1,0) [0|255] ""  PC
 SG_ S2P_Cfg4_HW_Ver_Byte15_23 : 48|8@1+ (1,0) [0|255] ""  PC
 SG_ S2P_Cfg4_HW_Ver_Byte16_23 : 56|8@1+ (1,0) [0|255] ""  PC

BO_ 2416307800 S2P_Cfg4__24: 8 SBMU
 SG_ S2P_Cfg4_HW_Ver_Byte9_24 : 0|8@1+ (1,0) [0|255] ""  PC
 SG_ S2P_Cfg4_HW_Ver_Byte10_24 : 8|8@1+ (1,0) [0|255] ""  PC
 SG_ S2P_Cfg4_HW_Ver_Byte11_24 : 16|8@1+ (1,0) [0|255] ""  PC
 SG_ S2P_Cfg4_HW_Ver_Byte12_24 : 24|8@1+ (1,0) [0|255] ""  PC
 SG_ S2P_Cfg4_HW_Ver_Byte13_24 : 32|8@1+ (1,0) [0|255] ""  PC
 SG_ S2P_Cfg4_HW_Ver_Byte14_24 : 40|8@1+ (1,0) [0|255] ""  PC
 SG_ S2P_Cfg4_HW_Ver_Byte15_24 : 48|8@1+ (1,0) [0|255] ""  PC
 SG_ S2P_Cfg4_HW_Ver_Byte16_24 : 56|8@1+ (1,0) [0|255] ""  PC

BO_ 2416307801 S2P_Cfg4__25: 8 SBMU
 SG_ S2P_Cfg4_HW_Ver_Byte9_25 : 0|8@1+ (1,0) [0|255] ""  PC
 SG_ S2P_Cfg4_HW_Ver_Byte10_25 : 8|8@1+ (1,0) [0|255] ""  PC
 SG_ S2P_Cfg4_HW_Ver_Byte11_25 : 16|8@1+ (1,0) [0|255] ""  PC
 SG_ S2P_Cfg4_HW_Ver_Byte12_25 : 24|8@1+ (1,0) [0|255] ""  PC
 SG_ S2P_Cfg4_HW_Ver_Byte13_25 : 32|8@1+ (1,0) [0|255] ""  PC
 SG_ S2P_Cfg4_HW_Ver_Byte14_25 : 40|8@1+ (1,0) [0|255] ""  PC
 SG_ S2P_Cfg4_HW_Ver_Byte15_25 : 48|8@1+ (1,0) [0|255] ""  PC
 SG_ S2P_Cfg4_HW_Ver_Byte16_25 : 56|8@1+ (1,0) [0|255] ""  PC

BO_ 2416307802 S2P_Cfg4__26: 8 SBMU
 SG_ S2P_Cfg4_HW_Ver_Byte9_26 : 0|8@1+ (1,0) [0|255] ""  PC
 SG_ S2P_Cfg4_HW_Ver_Byte10_26 : 8|8@1+ (1,0) [0|255] ""  PC
 SG_ S2P_Cfg4_HW_Ver_Byte11_26 : 16|8@1+ (1,0) [0|255] ""  PC
 SG_ S2P_Cfg4_HW_Ver_Byte12_26 : 24|8@1+ (1,0) [0|255] ""  PC
 SG_ S2P_Cfg4_HW_Ver_Byte13_26 : 32|8@1+ (1,0) [0|255] ""  PC
 SG_ S2P_Cfg4_HW_Ver_Byte14_26 : 40|8@1+ (1,0) [0|255] ""  PC
 SG_ S2P_Cfg4_HW_Ver_Byte15_26 : 48|8@1+ (1,0) [0|255] ""  PC
 SG_ S2P_Cfg4_HW_Ver_Byte16_26 : 56|8@1+ (1,0) [0|255] ""  PC

BO_ 2416307803 S2P_Cfg4__27: 8 SBMU
 SG_ S2P_Cfg4_HW_Ver_Byte9_27 : 0|8@1+ (1,0) [0|255] ""  PC
 SG_ S2P_Cfg4_HW_Ver_Byte10_27 : 8|8@1+ (1,0) [0|255] ""  PC
 SG_ S2P_Cfg4_HW_Ver_Byte11_27 : 16|8@1+ (1,0) [0|255] ""  PC
 SG_ S2P_Cfg4_HW_Ver_Byte12_27 : 24|8@1+ (1,0) [0|255] ""  PC
 SG_ S2P_Cfg4_HW_Ver_Byte13_27 : 32|8@1+ (1,0) [0|255] ""  PC
 SG_ S2P_Cfg4_HW_Ver_Byte14_27 : 40|8@1+ (1,0) [0|255] ""  PC
 SG_ S2P_Cfg4_HW_Ver_Byte15_27 : 48|8@1+ (1,0) [0|255] ""  PC
 SG_ S2P_Cfg4_HW_Ver_Byte16_27 : 56|8@1+ (1,0) [0|255] ""  PC

BO_ 2416307804 S2P_Cfg4__28: 8 SBMU
 SG_ S2P_Cfg4_HW_Ver_Byte9_28 : 0|8@1+ (1,0) [0|255] ""  PC
 SG_ S2P_Cfg4_HW_Ver_Byte10_28 : 8|8@1+ (1,0) [0|255] ""  PC
 SG_ S2P_Cfg4_HW_Ver_Byte11_28 : 16|8@1+ (1,0) [0|255] ""  PC
 SG_ S2P_Cfg4_HW_Ver_Byte12_28 : 24|8@1+ (1,0) [0|255] ""  PC
 SG_ S2P_Cfg4_HW_Ver_Byte13_28 : 32|8@1+ (1,0) [0|255] ""  PC
 SG_ S2P_Cfg4_HW_Ver_Byte14_28 : 40|8@1+ (1,0) [0|255] ""  PC
 SG_ S2P_Cfg4_HW_Ver_Byte15_28 : 48|8@1+ (1,0) [0|255] ""  PC
 SG_ S2P_Cfg4_HW_Ver_Byte16_28 : 56|8@1+ (1,0) [0|255] ""  PC

BO_ 2416307805 S2P_Cfg4__29: 8 SBMU
 SG_ S2P_Cfg4_HW_Ver_Byte9_29 : 0|8@1+ (1,0) [0|255] ""  PC
 SG_ S2P_Cfg4_HW_Ver_Byte10_29 : 8|8@1+ (1,0) [0|255] ""  PC
 SG_ S2P_Cfg4_HW_Ver_Byte11_29 : 16|8@1+ (1,0) [0|255] ""  PC
 SG_ S2P_Cfg4_HW_Ver_Byte12_29 : 24|8@1+ (1,0) [0|255] ""  PC
 SG_ S2P_Cfg4_HW_Ver_Byte13_29 : 32|8@1+ (1,0) [0|255] ""  PC
 SG_ S2P_Cfg4_HW_Ver_Byte14_29 : 40|8@1+ (1,0) [0|255] ""  PC
 SG_ S2P_Cfg4_HW_Ver_Byte15_29 : 48|8@1+ (1,0) [0|255] ""  PC
 SG_ S2P_Cfg4_HW_Ver_Byte16_29 : 56|8@1+ (1,0) [0|255] ""  PC

BO_ 2416307806 S2P_Cfg4__30: 8 SBMU
 SG_ S2P_Cfg4_HW_Ver_Byte9_30 : 0|8@1+ (1,0) [0|255] ""  PC
 SG_ S2P_Cfg4_HW_Ver_Byte10_30 : 8|8@1+ (1,0) [0|255] ""  PC
 SG_ S2P_Cfg4_HW_Ver_Byte11_30 : 16|8@1+ (1,0) [0|255] ""  PC
 SG_ S2P_Cfg4_HW_Ver_Byte12_30 : 24|8@1+ (1,0) [0|255] ""  PC
 SG_ S2P_Cfg4_HW_Ver_Byte13_30 : 32|8@1+ (1,0) [0|255] ""  PC
 SG_ S2P_Cfg4_HW_Ver_Byte14_30 : 40|8@1+ (1,0) [0|255] ""  PC
 SG_ S2P_Cfg4_HW_Ver_Byte15_30 : 48|8@1+ (1,0) [0|255] ""  PC
 SG_ S2P_Cfg4_HW_Ver_Byte16_30 : 56|8@1+ (1,0) [0|255] ""  PC

BO_ 2416307807 S2P_Cfg4__31: 8 SBMU
 SG_ S2P_Cfg4_HW_Ver_Byte9_31 : 0|8@1+ (1,0) [0|255] ""  PC
 SG_ S2P_Cfg4_HW_Ver_Byte10_31 : 8|8@1+ (1,0) [0|255] ""  PC
 SG_ S2P_Cfg4_HW_Ver_Byte11_31 : 16|8@1+ (1,0) [0|255] ""  PC
 SG_ S2P_Cfg4_HW_Ver_Byte12_31 : 24|8@1+ (1,0) [0|255] ""  PC
 SG_ S2P_Cfg4_HW_Ver_Byte13_31 : 32|8@1+ (1,0) [0|255] ""  PC
 SG_ S2P_Cfg4_HW_Ver_Byte14_31 : 40|8@1+ (1,0) [0|255] ""  PC
 SG_ S2P_Cfg4_HW_Ver_Byte15_31 : 48|8@1+ (1,0) [0|255] ""  PC
 SG_ S2P_Cfg4_HW_Ver_Byte16_31 : 56|8@1+ (1,0) [0|255] ""  PC

BO_ 2416307808 S2P_Cfg4__32: 8 SBMU
 SG_ S2P_Cfg4_HW_Ver_Byte9_32 : 0|8@1+ (1,0) [0|255] ""  PC
 SG_ S2P_Cfg4_HW_Ver_Byte10_32 : 8|8@1+ (1,0) [0|255] ""  PC
 SG_ S2P_Cfg4_HW_Ver_Byte11_32 : 16|8@1+ (1,0) [0|255] ""  PC
 SG_ S2P_Cfg4_HW_Ver_Byte12_32 : 24|8@1+ (1,0) [0|255] ""  PC
 SG_ S2P_Cfg4_HW_Ver_Byte13_32 : 32|8@1+ (1,0) [0|255] ""  PC
 SG_ S2P_Cfg4_HW_Ver_Byte14_32 : 40|8@1+ (1,0) [0|255] ""  PC
 SG_ S2P_Cfg4_HW_Ver_Byte15_32 : 48|8@1+ (1,0) [0|255] ""  PC
 SG_ S2P_Cfg4_HW_Ver_Byte16_32 : 56|8@1+ (1,0) [0|255] ""  PC

BO_ 2416307809 S2P_Cfg4__33: 8 SBMU
 SG_ S2P_Cfg4_HW_Ver_Byte9_33 : 0|8@1+ (1,0) [0|255] ""  PC
 SG_ S2P_Cfg4_HW_Ver_Byte10_33 : 8|8@1+ (1,0) [0|255] ""  PC
 SG_ S2P_Cfg4_HW_Ver_Byte11_33 : 16|8@1+ (1,0) [0|255] ""  PC
 SG_ S2P_Cfg4_HW_Ver_Byte12_33 : 24|8@1+ (1,0) [0|255] ""  PC
 SG_ S2P_Cfg4_HW_Ver_Byte13_33 : 32|8@1+ (1,0) [0|255] ""  PC
 SG_ S2P_Cfg4_HW_Ver_Byte14_33 : 40|8@1+ (1,0) [0|255] ""  PC
 SG_ S2P_Cfg4_HW_Ver_Byte15_33 : 48|8@1+ (1,0) [0|255] ""  PC
 SG_ S2P_Cfg4_HW_Ver_Byte16_33 : 56|8@1+ (1,0) [0|255] ""  PC

BO_ 2416307810 S2P_Cfg4__34: 8 SBMU
 SG_ S2P_Cfg4_HW_Ver_Byte9_34 : 0|8@1+ (1,0) [0|255] ""  PC
 SG_ S2P_Cfg4_HW_Ver_Byte10_34 : 8|8@1+ (1,0) [0|255] ""  PC
 SG_ S2P_Cfg4_HW_Ver_Byte11_34 : 16|8@1+ (1,0) [0|255] ""  PC
 SG_ S2P_Cfg4_HW_Ver_Byte12_34 : 24|8@1+ (1,0) [0|255] ""  PC
 SG_ S2P_Cfg4_HW_Ver_Byte13_34 : 32|8@1+ (1,0) [0|255] ""  PC
 SG_ S2P_Cfg4_HW_Ver_Byte14_34 : 40|8@1+ (1,0) [0|255] ""  PC
 SG_ S2P_Cfg4_HW_Ver_Byte15_34 : 48|8@1+ (1,0) [0|255] ""  PC
 SG_ S2P_Cfg4_HW_Ver_Byte16_34 : 56|8@1+ (1,0) [0|255] ""  PC

BO_ 2416307811 S2P_Cfg4__35: 8 SBMU
 SG_ S2P_Cfg4_HW_Ver_Byte9_35 : 0|8@1+ (1,0) [0|255] ""  PC
 SG_ S2P_Cfg4_HW_Ver_Byte10_35 : 8|8@1+ (1,0) [0|255] ""  PC
 SG_ S2P_Cfg4_HW_Ver_Byte11_35 : 16|8@1+ (1,0) [0|255] ""  PC
 SG_ S2P_Cfg4_HW_Ver_Byte12_35 : 24|8@1+ (1,0) [0|255] ""  PC
 SG_ S2P_Cfg4_HW_Ver_Byte13_35 : 32|8@1+ (1,0) [0|255] ""  PC
 SG_ S2P_Cfg4_HW_Ver_Byte14_35 : 40|8@1+ (1,0) [0|255] ""  PC
 SG_ S2P_Cfg4_HW_Ver_Byte15_35 : 48|8@1+ (1,0) [0|255] ""  PC
 SG_ S2P_Cfg4_HW_Ver_Byte16_35 : 56|8@1+ (1,0) [0|255] ""  PC

BO_ 2416307812 S2P_Cfg4__36: 8 SBMU
 SG_ S2P_Cfg4_HW_Ver_Byte9_36 : 0|8@1+ (1,0) [0|255] ""  PC
 SG_ S2P_Cfg4_HW_Ver_Byte10_36 : 8|8@1+ (1,0) [0|255] ""  PC
 SG_ S2P_Cfg4_HW_Ver_Byte11_36 : 16|8@1+ (1,0) [0|255] ""  PC
 SG_ S2P_Cfg4_HW_Ver_Byte12_36 : 24|8@1+ (1,0) [0|255] ""  PC
 SG_ S2P_Cfg4_HW_Ver_Byte13_36 : 32|8@1+ (1,0) [0|255] ""  PC
 SG_ S2P_Cfg4_HW_Ver_Byte14_36 : 40|8@1+ (1,0) [0|255] ""  PC
 SG_ S2P_Cfg4_HW_Ver_Byte15_36 : 48|8@1+ (1,0) [0|255] ""  PC
 SG_ S2P_Cfg4_HW_Ver_Byte16_36 : 56|8@1+ (1,0) [0|255] ""  PC

BO_ 2416307813 S2P_Cfg4__37: 8 SBMU
 SG_ S2P_Cfg4_HW_Ver_Byte9_37 : 0|8@1+ (1,0) [0|255] ""  PC
 SG_ S2P_Cfg4_HW_Ver_Byte10_37 : 8|8@1+ (1,0) [0|255] ""  PC
 SG_ S2P_Cfg4_HW_Ver_Byte11_37 : 16|8@1+ (1,0) [0|255] ""  PC
 SG_ S2P_Cfg4_HW_Ver_Byte12_37 : 24|8@1+ (1,0) [0|255] ""  PC
 SG_ S2P_Cfg4_HW_Ver_Byte13_37 : 32|8@1+ (1,0) [0|255] ""  PC
 SG_ S2P_Cfg4_HW_Ver_Byte14_37 : 40|8@1+ (1,0) [0|255] ""  PC
 SG_ S2P_Cfg4_HW_Ver_Byte15_37 : 48|8@1+ (1,0) [0|255] ""  PC
 SG_ S2P_Cfg4_HW_Ver_Byte16_37 : 56|8@1+ (1,0) [0|255] ""  PC

BO_ 2416307814 S2P_Cfg4__38: 8 SBMU
 SG_ S2P_Cfg4_HW_Ver_Byte9_38 : 0|8@1+ (1,0) [0|255] ""  PC
 SG_ S2P_Cfg4_HW_Ver_Byte10_38 : 8|8@1+ (1,0) [0|255] ""  PC
 SG_ S2P_Cfg4_HW_Ver_Byte11_38 : 16|8@1+ (1,0) [0|255] ""  PC
 SG_ S2P_Cfg4_HW_Ver_Byte12_38 : 24|8@1+ (1,0) [0|255] ""  PC
 SG_ S2P_Cfg4_HW_Ver_Byte13_38 : 32|8@1+ (1,0) [0|255] ""  PC
 SG_ S2P_Cfg4_HW_Ver_Byte14_38 : 40|8@1+ (1,0) [0|255] ""  PC
 SG_ S2P_Cfg4_HW_Ver_Byte15_38 : 48|8@1+ (1,0) [0|255] ""  PC
 SG_ S2P_Cfg4_HW_Ver_Byte16_38 : 56|8@1+ (1,0) [0|255] ""  PC

BO_ 2416307815 S2P_Cfg4__39: 8 SBMU
 SG_ S2P_Cfg4_HW_Ver_Byte9_39 : 0|8@1+ (1,0) [0|255] ""  PC
 SG_ S2P_Cfg4_HW_Ver_Byte10_39 : 8|8@1+ (1,0) [0|255] ""  PC
 SG_ S2P_Cfg4_HW_Ver_Byte11_39 : 16|8@1+ (1,0) [0|255] ""  PC
 SG_ S2P_Cfg4_HW_Ver_Byte12_39 : 24|8@1+ (1,0) [0|255] ""  PC
 SG_ S2P_Cfg4_HW_Ver_Byte13_39 : 32|8@1+ (1,0) [0|255] ""  PC
 SG_ S2P_Cfg4_HW_Ver_Byte14_39 : 40|8@1+ (1,0) [0|255] ""  PC
 SG_ S2P_Cfg4_HW_Ver_Byte15_39 : 48|8@1+ (1,0) [0|255] ""  PC
 SG_ S2P_Cfg4_HW_Ver_Byte16_39 : 56|8@1+ (1,0) [0|255] ""  PC

BO_ 2416307816 S2P_Cfg4__40: 8 SBMU
 SG_ S2P_Cfg4_HW_Ver_Byte9_40 : 0|8@1+ (1,0) [0|255] ""  PC
 SG_ S2P_Cfg4_HW_Ver_Byte10_40 : 8|8@1+ (1,0) [0|255] ""  PC
 SG_ S2P_Cfg4_HW_Ver_Byte11_40 : 16|8@1+ (1,0) [0|255] ""  PC
 SG_ S2P_Cfg4_HW_Ver_Byte12_40 : 24|8@1+ (1,0) [0|255] ""  PC
 SG_ S2P_Cfg4_HW_Ver_Byte13_40 : 32|8@1+ (1,0) [0|255] ""  PC
 SG_ S2P_Cfg4_HW_Ver_Byte14_40 : 40|8@1+ (1,0) [0|255] ""  PC
 SG_ S2P_Cfg4_HW_Ver_Byte15_40 : 48|8@1+ (1,0) [0|255] ""  PC
 SG_ S2P_Cfg4_HW_Ver_Byte16_40 : 56|8@1+ (1,0) [0|255] ""  PC

BO_ 2416307817 S2P_Cfg4__41: 8 SBMU
 SG_ S2P_Cfg4_HW_Ver_Byte9_41 : 0|8@1+ (1,0) [0|255] ""  PC
 SG_ S2P_Cfg4_HW_Ver_Byte10_41 : 8|8@1+ (1,0) [0|255] ""  PC
 SG_ S2P_Cfg4_HW_Ver_Byte11_41 : 16|8@1+ (1,0) [0|255] ""  PC
 SG_ S2P_Cfg4_HW_Ver_Byte12_41 : 24|8@1+ (1,0) [0|255] ""  PC
 SG_ S2P_Cfg4_HW_Ver_Byte13_41 : 32|8@1+ (1,0) [0|255] ""  PC
 SG_ S2P_Cfg4_HW_Ver_Byte14_41 : 40|8@1+ (1,0) [0|255] ""  PC
 SG_ S2P_Cfg4_HW_Ver_Byte15_41 : 48|8@1+ (1,0) [0|255] ""  PC
 SG_ S2P_Cfg4_HW_Ver_Byte16_41 : 56|8@1+ (1,0) [0|255] ""  PC

BO_ 2416307818 S2P_Cfg4__42: 8 SBMU
 SG_ S2P_Cfg4_HW_Ver_Byte9_42 : 0|8@1+ (1,0) [0|255] ""  PC
 SG_ S2P_Cfg4_HW_Ver_Byte10_42 : 8|8@1+ (1,0) [0|255] ""  PC
 SG_ S2P_Cfg4_HW_Ver_Byte11_42 : 16|8@1+ (1,0) [0|255] ""  PC
 SG_ S2P_Cfg4_HW_Ver_Byte12_42 : 24|8@1+ (1,0) [0|255] ""  PC
 SG_ S2P_Cfg4_HW_Ver_Byte13_42 : 32|8@1+ (1,0) [0|255] ""  PC
 SG_ S2P_Cfg4_HW_Ver_Byte14_42 : 40|8@1+ (1,0) [0|255] ""  PC
 SG_ S2P_Cfg4_HW_Ver_Byte15_42 : 48|8@1+ (1,0) [0|255] ""  PC
 SG_ S2P_Cfg4_HW_Ver_Byte16_42 : 56|8@1+ (1,0) [0|255] ""  PC

BO_ 2416307819 S2P_Cfg4__43: 8 SBMU
 SG_ S2P_Cfg4_HW_Ver_Byte9_43 : 0|8@1+ (1,0) [0|255] ""  PC
 SG_ S2P_Cfg4_HW_Ver_Byte10_43 : 8|8@1+ (1,0) [0|255] ""  PC
 SG_ S2P_Cfg4_HW_Ver_Byte11_43 : 16|8@1+ (1,0) [0|255] ""  PC
 SG_ S2P_Cfg4_HW_Ver_Byte12_43 : 24|8@1+ (1,0) [0|255] ""  PC
 SG_ S2P_Cfg4_HW_Ver_Byte13_43 : 32|8@1+ (1,0) [0|255] ""  PC
 SG_ S2P_Cfg4_HW_Ver_Byte14_43 : 40|8@1+ (1,0) [0|255] ""  PC
 SG_ S2P_Cfg4_HW_Ver_Byte15_43 : 48|8@1+ (1,0) [0|255] ""  PC
 SG_ S2P_Cfg4_HW_Ver_Byte16_43 : 56|8@1+ (1,0) [0|255] ""  PC

BO_ 2416307820 S2P_Cfg4__44: 8 SBMU
 SG_ S2P_Cfg4_HW_Ver_Byte9_44 : 0|8@1+ (1,0) [0|255] ""  PC
 SG_ S2P_Cfg4_HW_Ver_Byte10_44 : 8|8@1+ (1,0) [0|255] ""  PC
 SG_ S2P_Cfg4_HW_Ver_Byte11_44 : 16|8@1+ (1,0) [0|255] ""  PC
 SG_ S2P_Cfg4_HW_Ver_Byte12_44 : 24|8@1+ (1,0) [0|255] ""  PC
 SG_ S2P_Cfg4_HW_Ver_Byte13_44 : 32|8@1+ (1,0) [0|255] ""  PC
 SG_ S2P_Cfg4_HW_Ver_Byte14_44 : 40|8@1+ (1,0) [0|255] ""  PC
 SG_ S2P_Cfg4_HW_Ver_Byte15_44 : 48|8@1+ (1,0) [0|255] ""  PC
 SG_ S2P_Cfg4_HW_Ver_Byte16_44 : 56|8@1+ (1,0) [0|255] ""  PC

BO_ 2416307821 S2P_Cfg4__45: 8 SBMU
 SG_ S2P_Cfg4_HW_Ver_Byte9_45 : 0|8@1+ (1,0) [0|255] ""  PC
 SG_ S2P_Cfg4_HW_Ver_Byte10_45 : 8|8@1+ (1,0) [0|255] ""  PC
 SG_ S2P_Cfg4_HW_Ver_Byte11_45 : 16|8@1+ (1,0) [0|255] ""  PC
 SG_ S2P_Cfg4_HW_Ver_Byte12_45 : 24|8@1+ (1,0) [0|255] ""  PC
 SG_ S2P_Cfg4_HW_Ver_Byte13_45 : 32|8@1+ (1,0) [0|255] ""  PC
 SG_ S2P_Cfg4_HW_Ver_Byte14_45 : 40|8@1+ (1,0) [0|255] ""  PC
 SG_ S2P_Cfg4_HW_Ver_Byte15_45 : 48|8@1+ (1,0) [0|255] ""  PC
 SG_ S2P_Cfg4_HW_Ver_Byte16_45 : 56|8@1+ (1,0) [0|255] ""  PC

BO_ 2416307822 S2P_Cfg4__46: 8 SBMU
 SG_ S2P_Cfg4_HW_Ver_Byte9_46 : 0|8@1+ (1,0) [0|255] ""  PC
 SG_ S2P_Cfg4_HW_Ver_Byte10_46 : 8|8@1+ (1,0) [0|255] ""  PC
 SG_ S2P_Cfg4_HW_Ver_Byte11_46 : 16|8@1+ (1,0) [0|255] ""  PC
 SG_ S2P_Cfg4_HW_Ver_Byte12_46 : 24|8@1+ (1,0) [0|255] ""  PC
 SG_ S2P_Cfg4_HW_Ver_Byte13_46 : 32|8@1+ (1,0) [0|255] ""  PC
 SG_ S2P_Cfg4_HW_Ver_Byte14_46 : 40|8@1+ (1,0) [0|255] ""  PC
 SG_ S2P_Cfg4_HW_Ver_Byte15_46 : 48|8@1+ (1,0) [0|255] ""  PC
 SG_ S2P_Cfg4_HW_Ver_Byte16_46 : 56|8@1+ (1,0) [0|255] ""  PC

BO_ 2416307823 S2P_Cfg4__47: 8 SBMU
 SG_ S2P_Cfg4_HW_Ver_Byte9_47 : 0|8@1+ (1,0) [0|255] ""  PC
 SG_ S2P_Cfg4_HW_Ver_Byte10_47 : 8|8@1+ (1,0) [0|255] ""  PC
 SG_ S2P_Cfg4_HW_Ver_Byte11_47 : 16|8@1+ (1,0) [0|255] ""  PC
 SG_ S2P_Cfg4_HW_Ver_Byte12_47 : 24|8@1+ (1,0) [0|255] ""  PC
 SG_ S2P_Cfg4_HW_Ver_Byte13_47 : 32|8@1+ (1,0) [0|255] ""  PC
 SG_ S2P_Cfg4_HW_Ver_Byte14_47 : 40|8@1+ (1,0) [0|255] ""  PC
 SG_ S2P_Cfg4_HW_Ver_Byte15_47 : 48|8@1+ (1,0) [0|255] ""  PC
 SG_ S2P_Cfg4_HW_Ver_Byte16_47 : 56|8@1+ (1,0) [0|255] ""  PC

BO_ 2416307824 S2P_Cfg4__48: 8 SBMU
 SG_ S2P_Cfg4_HW_Ver_Byte9_48 : 0|8@1+ (1,0) [0|255] ""  PC
 SG_ S2P_Cfg4_HW_Ver_Byte10_48 : 8|8@1+ (1,0) [0|255] ""  PC
 SG_ S2P_Cfg4_HW_Ver_Byte11_48 : 16|8@1+ (1,0) [0|255] ""  PC
 SG_ S2P_Cfg4_HW_Ver_Byte12_48 : 24|8@1+ (1,0) [0|255] ""  PC
 SG_ S2P_Cfg4_HW_Ver_Byte13_48 : 32|8@1+ (1,0) [0|255] ""  PC
 SG_ S2P_Cfg4_HW_Ver_Byte14_48 : 40|8@1+ (1,0) [0|255] ""  PC
 SG_ S2P_Cfg4_HW_Ver_Byte15_48 : 48|8@1+ (1,0) [0|255] ""  PC
 SG_ S2P_Cfg4_HW_Ver_Byte16_48 : 56|8@1+ (1,0) [0|255] ""  PC

BO_ 2416307825 S2P_Cfg4__49: 8 SBMU
 SG_ S2P_Cfg4_HW_Ver_Byte9_49 : 0|8@1+ (1,0) [0|255] ""  PC
 SG_ S2P_Cfg4_HW_Ver_Byte10_49 : 8|8@1+ (1,0) [0|255] ""  PC
 SG_ S2P_Cfg4_HW_Ver_Byte11_49 : 16|8@1+ (1,0) [0|255] ""  PC
 SG_ S2P_Cfg4_HW_Ver_Byte12_49 : 24|8@1+ (1,0) [0|255] ""  PC
 SG_ S2P_Cfg4_HW_Ver_Byte13_49 : 32|8@1+ (1,0) [0|255] ""  PC
 SG_ S2P_Cfg4_HW_Ver_Byte14_49 : 40|8@1+ (1,0) [0|255] ""  PC
 SG_ S2P_Cfg4_HW_Ver_Byte15_49 : 48|8@1+ (1,0) [0|255] ""  PC
 SG_ S2P_Cfg4_HW_Ver_Byte16_49 : 56|8@1+ (1,0) [0|255] ""  PC

BO_ 2416307826 S2P_Cfg4__50: 8 SBMU
 SG_ S2P_Cfg4_HW_Ver_Byte9_50 : 0|8@1+ (1,0) [0|255] ""  PC
 SG_ S2P_Cfg4_HW_Ver_Byte10_50 : 8|8@1+ (1,0) [0|255] ""  PC
 SG_ S2P_Cfg4_HW_Ver_Byte11_50 : 16|8@1+ (1,0) [0|255] ""  PC
 SG_ S2P_Cfg4_HW_Ver_Byte12_50 : 24|8@1+ (1,0) [0|255] ""  PC
 SG_ S2P_Cfg4_HW_Ver_Byte13_50 : 32|8@1+ (1,0) [0|255] ""  PC
 SG_ S2P_Cfg4_HW_Ver_Byte14_50 : 40|8@1+ (1,0) [0|255] ""  PC
 SG_ S2P_Cfg4_HW_Ver_Byte15_50 : 48|8@1+ (1,0) [0|255] ""  PC
 SG_ S2P_Cfg4_HW_Ver_Byte16_50 : 56|8@1+ (1,0) [0|255] ""  PC

BO_ 2416307827 S2P_Cfg4__51: 8 SBMU
 SG_ S2P_Cfg4_HW_Ver_Byte9_51 : 0|8@1+ (1,0) [0|255] ""  PC
 SG_ S2P_Cfg4_HW_Ver_Byte10_51 : 8|8@1+ (1,0) [0|255] ""  PC
 SG_ S2P_Cfg4_HW_Ver_Byte11_51 : 16|8@1+ (1,0) [0|255] ""  PC
 SG_ S2P_Cfg4_HW_Ver_Byte12_51 : 24|8@1+ (1,0) [0|255] ""  PC
 SG_ S2P_Cfg4_HW_Ver_Byte13_51 : 32|8@1+ (1,0) [0|255] ""  PC
 SG_ S2P_Cfg4_HW_Ver_Byte14_51 : 40|8@1+ (1,0) [0|255] ""  PC
 SG_ S2P_Cfg4_HW_Ver_Byte15_51 : 48|8@1+ (1,0) [0|255] ""  PC
 SG_ S2P_Cfg4_HW_Ver_Byte16_51 : 56|8@1+ (1,0) [0|255] ""  PC

BO_ 2416307828 S2P_Cfg4__52: 8 SBMU
 SG_ S2P_Cfg4_HW_Ver_Byte9_52 : 0|8@1+ (1,0) [0|255] ""  PC
 SG_ S2P_Cfg4_HW_Ver_Byte10_52 : 8|8@1+ (1,0) [0|255] ""  PC
 SG_ S2P_Cfg4_HW_Ver_Byte11_52 : 16|8@1+ (1,0) [0|255] ""  PC
 SG_ S2P_Cfg4_HW_Ver_Byte12_52 : 24|8@1+ (1,0) [0|255] ""  PC
 SG_ S2P_Cfg4_HW_Ver_Byte13_52 : 32|8@1+ (1,0) [0|255] ""  PC
 SG_ S2P_Cfg4_HW_Ver_Byte14_52 : 40|8@1+ (1,0) [0|255] ""  PC
 SG_ S2P_Cfg4_HW_Ver_Byte15_52 : 48|8@1+ (1,0) [0|255] ""  PC
 SG_ S2P_Cfg4_HW_Ver_Byte16_52 : 56|8@1+ (1,0) [0|255] ""  PC

BO_ 2416307829 S2P_Cfg4__53: 8 SBMU
 SG_ S2P_Cfg4_HW_Ver_Byte9_53 : 0|8@1+ (1,0) [0|255] ""  PC
 SG_ S2P_Cfg4_HW_Ver_Byte10_53 : 8|8@1+ (1,0) [0|255] ""  PC
 SG_ S2P_Cfg4_HW_Ver_Byte11_53 : 16|8@1+ (1,0) [0|255] ""  PC
 SG_ S2P_Cfg4_HW_Ver_Byte12_53 : 24|8@1+ (1,0) [0|255] ""  PC
 SG_ S2P_Cfg4_HW_Ver_Byte13_53 : 32|8@1+ (1,0) [0|255] ""  PC
 SG_ S2P_Cfg4_HW_Ver_Byte14_53 : 40|8@1+ (1,0) [0|255] ""  PC
 SG_ S2P_Cfg4_HW_Ver_Byte15_53 : 48|8@1+ (1,0) [0|255] ""  PC
 SG_ S2P_Cfg4_HW_Ver_Byte16_53 : 56|8@1+ (1,0) [0|255] ""  PC

BO_ 2416307830 S2P_Cfg4__54: 8 SBMU
 SG_ S2P_Cfg4_HW_Ver_Byte9_54 : 0|8@1+ (1,0) [0|255] ""  PC
 SG_ S2P_Cfg4_HW_Ver_Byte10_54 : 8|8@1+ (1,0) [0|255] ""  PC
 SG_ S2P_Cfg4_HW_Ver_Byte11_54 : 16|8@1+ (1,0) [0|255] ""  PC
 SG_ S2P_Cfg4_HW_Ver_Byte12_54 : 24|8@1+ (1,0) [0|255] ""  PC
 SG_ S2P_Cfg4_HW_Ver_Byte13_54 : 32|8@1+ (1,0) [0|255] ""  PC
 SG_ S2P_Cfg4_HW_Ver_Byte14_54 : 40|8@1+ (1,0) [0|255] ""  PC
 SG_ S2P_Cfg4_HW_Ver_Byte15_54 : 48|8@1+ (1,0) [0|255] ""  PC
 SG_ S2P_Cfg4_HW_Ver_Byte16_54 : 56|8@1+ (1,0) [0|255] ""  PC

BO_ 2416307831 S2P_Cfg4__55: 8 SBMU
 SG_ S2P_Cfg4_HW_Ver_Byte9_55 : 0|8@1+ (1,0) [0|255] ""  PC
 SG_ S2P_Cfg4_HW_Ver_Byte10_55 : 8|8@1+ (1,0) [0|255] ""  PC
 SG_ S2P_Cfg4_HW_Ver_Byte11_55 : 16|8@1+ (1,0) [0|255] ""  PC
 SG_ S2P_Cfg4_HW_Ver_Byte12_55 : 24|8@1+ (1,0) [0|255] ""  PC
 SG_ S2P_Cfg4_HW_Ver_Byte13_55 : 32|8@1+ (1,0) [0|255] ""  PC
 SG_ S2P_Cfg4_HW_Ver_Byte14_55 : 40|8@1+ (1,0) [0|255] ""  PC
 SG_ S2P_Cfg4_HW_Ver_Byte15_55 : 48|8@1+ (1,0) [0|255] ""  PC
 SG_ S2P_Cfg4_HW_Ver_Byte16_55 : 56|8@1+ (1,0) [0|255] ""  PC

BO_ 2416307832 S2P_Cfg4__56: 8 SBMU
 SG_ S2P_Cfg4_HW_Ver_Byte9_56 : 0|8@1+ (1,0) [0|255] ""  PC
 SG_ S2P_Cfg4_HW_Ver_Byte10_56 : 8|8@1+ (1,0) [0|255] ""  PC
 SG_ S2P_Cfg4_HW_Ver_Byte11_56 : 16|8@1+ (1,0) [0|255] ""  PC
 SG_ S2P_Cfg4_HW_Ver_Byte12_56 : 24|8@1+ (1,0) [0|255] ""  PC
 SG_ S2P_Cfg4_HW_Ver_Byte13_56 : 32|8@1+ (1,0) [0|255] ""  PC
 SG_ S2P_Cfg4_HW_Ver_Byte14_56 : 40|8@1+ (1,0) [0|255] ""  PC
 SG_ S2P_Cfg4_HW_Ver_Byte15_56 : 48|8@1+ (1,0) [0|255] ""  PC
 SG_ S2P_Cfg4_HW_Ver_Byte16_56 : 56|8@1+ (1,0) [0|255] ""  PC

BO_ 2416307833 S2P_Cfg4__57: 8 SBMU
 SG_ S2P_Cfg4_HW_Ver_Byte9_57 : 0|8@1+ (1,0) [0|255] ""  PC
 SG_ S2P_Cfg4_HW_Ver_Byte10_57 : 8|8@1+ (1,0) [0|255] ""  PC
 SG_ S2P_Cfg4_HW_Ver_Byte11_57 : 16|8@1+ (1,0) [0|255] ""  PC
 SG_ S2P_Cfg4_HW_Ver_Byte12_57 : 24|8@1+ (1,0) [0|255] ""  PC
 SG_ S2P_Cfg4_HW_Ver_Byte13_57 : 32|8@1+ (1,0) [0|255] ""  PC
 SG_ S2P_Cfg4_HW_Ver_Byte14_57 : 40|8@1+ (1,0) [0|255] ""  PC
 SG_ S2P_Cfg4_HW_Ver_Byte15_57 : 48|8@1+ (1,0) [0|255] ""  PC
 SG_ S2P_Cfg4_HW_Ver_Byte16_57 : 56|8@1+ (1,0) [0|255] ""  PC

BO_ 2416307834 S2P_Cfg4__58: 8 SBMU
 SG_ S2P_Cfg4_HW_Ver_Byte9_58 : 0|8@1+ (1,0) [0|255] ""  PC
 SG_ S2P_Cfg4_HW_Ver_Byte10_58 : 8|8@1+ (1,0) [0|255] ""  PC
 SG_ S2P_Cfg4_HW_Ver_Byte11_58 : 16|8@1+ (1,0) [0|255] ""  PC
 SG_ S2P_Cfg4_HW_Ver_Byte12_58 : 24|8@1+ (1,0) [0|255] ""  PC
 SG_ S2P_Cfg4_HW_Ver_Byte13_58 : 32|8@1+ (1,0) [0|255] ""  PC
 SG_ S2P_Cfg4_HW_Ver_Byte14_58 : 40|8@1+ (1,0) [0|255] ""  PC
 SG_ S2P_Cfg4_HW_Ver_Byte15_58 : 48|8@1+ (1,0) [0|255] ""  PC
 SG_ S2P_Cfg4_HW_Ver_Byte16_58 : 56|8@1+ (1,0) [0|255] ""  PC

BO_ 2416307835 S2P_Cfg4__59: 8 SBMU
 SG_ S2P_Cfg4_HW_Ver_Byte9_59 : 0|8@1+ (1,0) [0|255] ""  PC
 SG_ S2P_Cfg4_HW_Ver_Byte10_59 : 8|8@1+ (1,0) [0|255] ""  PC
 SG_ S2P_Cfg4_HW_Ver_Byte11_59 : 16|8@1+ (1,0) [0|255] ""  PC
 SG_ S2P_Cfg4_HW_Ver_Byte12_59 : 24|8@1+ (1,0) [0|255] ""  PC
 SG_ S2P_Cfg4_HW_Ver_Byte13_59 : 32|8@1+ (1,0) [0|255] ""  PC
 SG_ S2P_Cfg4_HW_Ver_Byte14_59 : 40|8@1+ (1,0) [0|255] ""  PC
 SG_ S2P_Cfg4_HW_Ver_Byte15_59 : 48|8@1+ (1,0) [0|255] ""  PC
 SG_ S2P_Cfg4_HW_Ver_Byte16_59 : 56|8@1+ (1,0) [0|255] ""  PC

BO_ 2416307836 S2P_Cfg4__60: 8 SBMU
 SG_ S2P_Cfg4_HW_Ver_Byte9_60 : 0|8@1+ (1,0) [0|255] ""  PC
 SG_ S2P_Cfg4_HW_Ver_Byte10_60 : 8|8@1+ (1,0) [0|255] ""  PC
 SG_ S2P_Cfg4_HW_Ver_Byte11_60 : 16|8@1+ (1,0) [0|255] ""  PC
 SG_ S2P_Cfg4_HW_Ver_Byte12_60 : 24|8@1+ (1,0) [0|255] ""  PC
 SG_ S2P_Cfg4_HW_Ver_Byte13_60 : 32|8@1+ (1,0) [0|255] ""  PC
 SG_ S2P_Cfg4_HW_Ver_Byte14_60 : 40|8@1+ (1,0) [0|255] ""  PC
 SG_ S2P_Cfg4_HW_Ver_Byte15_60 : 48|8@1+ (1,0) [0|255] ""  PC
 SG_ S2P_Cfg4_HW_Ver_Byte16_60 : 56|8@1+ (1,0) [0|255] ""  PC

BO_ 2416307837 S2P_Cfg4__61: 8 SBMU
 SG_ S2P_Cfg4_HW_Ver_Byte9_61 : 0|8@1+ (1,0) [0|255] ""  PC
 SG_ S2P_Cfg4_HW_Ver_Byte10_61 : 8|8@1+ (1,0) [0|255] ""  PC
 SG_ S2P_Cfg4_HW_Ver_Byte11_61 : 16|8@1+ (1,0) [0|255] ""  PC
 SG_ S2P_Cfg4_HW_Ver_Byte12_61 : 24|8@1+ (1,0) [0|255] ""  PC
 SG_ S2P_Cfg4_HW_Ver_Byte13_61 : 32|8@1+ (1,0) [0|255] ""  PC
 SG_ S2P_Cfg4_HW_Ver_Byte14_61 : 40|8@1+ (1,0) [0|255] ""  PC
 SG_ S2P_Cfg4_HW_Ver_Byte15_61 : 48|8@1+ (1,0) [0|255] ""  PC
 SG_ S2P_Cfg4_HW_Ver_Byte16_61 : 56|8@1+ (1,0) [0|255] ""  PC

BO_ 2416307838 S2P_Cfg4__62: 8 SBMU
 SG_ S2P_Cfg4_HW_Ver_Byte9_62 : 0|8@1+ (1,0) [0|255] ""  PC
 SG_ S2P_Cfg4_HW_Ver_Byte10_62 : 8|8@1+ (1,0) [0|255] ""  PC
 SG_ S2P_Cfg4_HW_Ver_Byte11_62 : 16|8@1+ (1,0) [0|255] ""  PC
 SG_ S2P_Cfg4_HW_Ver_Byte12_62 : 24|8@1+ (1,0) [0|255] ""  PC
 SG_ S2P_Cfg4_HW_Ver_Byte13_62 : 32|8@1+ (1,0) [0|255] ""  PC
 SG_ S2P_Cfg4_HW_Ver_Byte14_62 : 40|8@1+ (1,0) [0|255] ""  PC
 SG_ S2P_Cfg4_HW_Ver_Byte15_62 : 48|8@1+ (1,0) [0|255] ""  PC
 SG_ S2P_Cfg4_HW_Ver_Byte16_62 : 56|8@1+ (1,0) [0|255] ""  PC

BO_ 2416307839 S2P_Cfg4__63: 8 SBMU
 SG_ S2P_Cfg4_HW_Ver_Byte9_63 : 0|8@1+ (1,0) [0|255] ""  PC
 SG_ S2P_Cfg4_HW_Ver_Byte10_63 : 8|8@1+ (1,0) [0|255] ""  PC
 SG_ S2P_Cfg4_HW_Ver_Byte11_63 : 16|8@1+ (1,0) [0|255] ""  PC
 SG_ S2P_Cfg4_HW_Ver_Byte12_63 : 24|8@1+ (1,0) [0|255] ""  PC
 SG_ S2P_Cfg4_HW_Ver_Byte13_63 : 32|8@1+ (1,0) [0|255] ""  PC
 SG_ S2P_Cfg4_HW_Ver_Byte14_63 : 40|8@1+ (1,0) [0|255] ""  PC
 SG_ S2P_Cfg4_HW_Ver_Byte15_63 : 48|8@1+ (1,0) [0|255] ""  PC
 SG_ S2P_Cfg4_HW_Ver_Byte16_63 : 56|8@1+ (1,0) [0|255] ""  PC

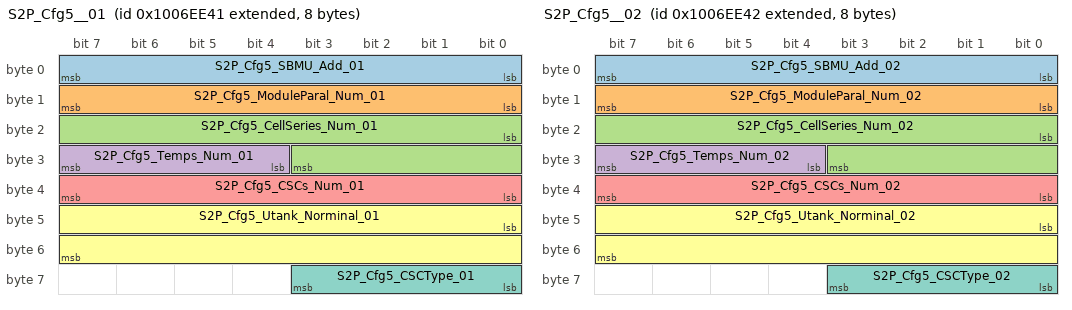
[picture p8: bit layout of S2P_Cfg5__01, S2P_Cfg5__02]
BO_ 2416373313 S2P_Cfg5__01: 8 SBMU
 SG_ S2P_Cfg5_SBMU_Add_01 : 0|8@1+ (1,0) [0|255] ""  PC
 SG_ S2P_Cfg5_ModuleParal_Num_01 : 8|8@1+ (1,0) [0|255] ""  PC
 SG_ S2P_Cfg5_CellSeries_Num_01 : 16|12@1+ (1,0) [0|4095] ""  PC
 SG_ S2P_Cfg5_Temps_Num_01 : 28|4@1+ (1,0) [0|15] ""  PC
 SG_ S2P_Cfg5_CSCs_Num_01 : 32|8@1+ (1,0) [0|255] ""  PC
 SG_ S2P_Cfg5_Utank_Norminal_01 : 40|16@1+ (0.1,0) [0|6553.5] "V"  PC
 SG_ S2P_Cfg5_CSCType_01 : 56|4@1+ (1,0) [0|15] ""  PC

BO_ 2416373314 S2P_Cfg5__02: 8 SBMU
 SG_ S2P_Cfg5_SBMU_Add_02 : 0|8@1+ (1,0) [0|255] ""  PC
 SG_ S2P_Cfg5_ModuleParal_Num_02 : 8|8@1+ (1,0) [0|255] ""  PC
 SG_ S2P_Cfg5_CellSeries_Num_02 : 16|12@1+ (1,0) [0|4095] ""  PC
 SG_ S2P_Cfg5_Temps_Num_02 : 28|4@1+ (1,0) [0|15] ""  PC
 SG_ S2P_Cfg5_CSCs_Num_02 : 32|8@1+ (1,0) [0|255] ""  PC
 SG_ S2P_Cfg5_Utank_Norminal_02 : 40|16@1+ (0.1,0) [0|6553.5] "V"  PC
 SG_ S2P_Cfg5_CSCType_02 : 56|4@1+ (1,0) [0|15] ""  PC

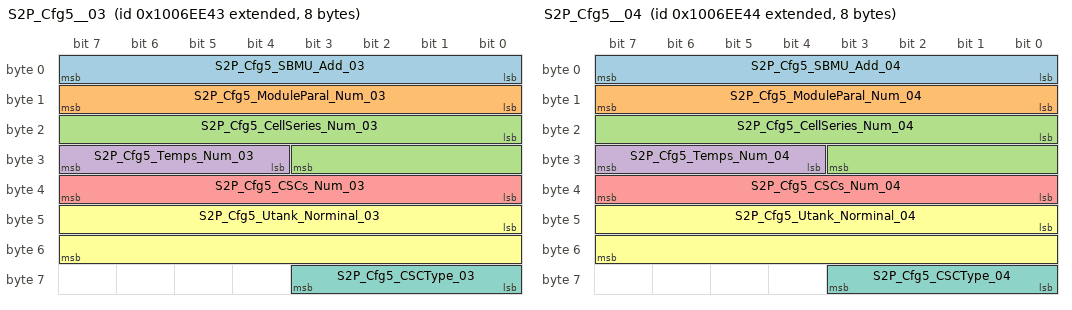
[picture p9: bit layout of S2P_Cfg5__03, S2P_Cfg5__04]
BO_ 2416373315 S2P_Cfg5__03: 8 SBMU
 SG_ S2P_Cfg5_SBMU_Add_03 : 0|8@1+ (1,0) [0|255] ""  PC
 SG_ S2P_Cfg5_ModuleParal_Num_03 : 8|8@1+ (1,0) [0|255] ""  PC
 SG_ S2P_Cfg5_CellSeries_Num_03 : 16|12@1+ (1,0) [0|4095] ""  PC
 SG_ S2P_Cfg5_Temps_Num_03 : 28|4@1+ (1,0) [0|15] ""  PC
 SG_ S2P_Cfg5_CSCs_Num_03 : 32|8@1+ (1,0) [0|255] ""  PC
 SG_ S2P_Cfg5_Utank_Norminal_03 : 40|16@1+ (0.1,0) [0|6553.5] "V"  PC
 SG_ S2P_Cfg5_CSCType_03 : 56|4@1+ (1,0) [0|15] ""  PC

BO_ 2416373316 S2P_Cfg5__04: 8 SBMU
 SG_ S2P_Cfg5_SBMU_Add_04 : 0|8@1+ (1,0) [0|255] ""  PC
 SG_ S2P_Cfg5_ModuleParal_Num_04 : 8|8@1+ (1,0) [0|255] ""  PC
 SG_ S2P_Cfg5_CellSeries_Num_04 : 16|12@1+ (1,0) [0|4095] ""  PC
 SG_ S2P_Cfg5_Temps_Num_04 : 28|4@1+ (1,0) [0|15] ""  PC
 SG_ S2P_Cfg5_CSCs_Num_04 : 32|8@1+ (1,0) [0|255] ""  PC
 SG_ S2P_Cfg5_Utank_Norminal_04 : 40|16@1+ (0.1,0) [0|6553.5] "V"  PC
 SG_ S2P_Cfg5_CSCType_04 : 56|4@1+ (1,0) [0|15] ""  PC

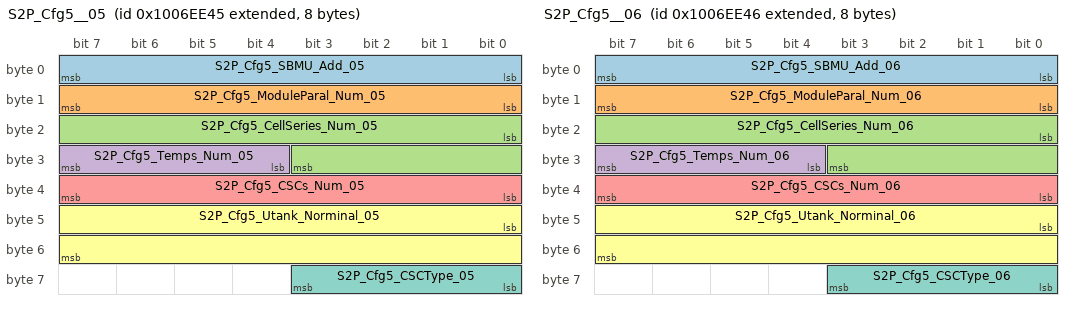
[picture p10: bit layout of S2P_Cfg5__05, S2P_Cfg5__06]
BO_ 2416373317 S2P_Cfg5__05: 8 SBMU
 SG_ S2P_Cfg5_SBMU_Add_05 : 0|8@1+ (1,0) [0|255] ""  PC
 SG_ S2P_Cfg5_ModuleParal_Num_05 : 8|8@1+ (1,0) [0|255] ""  PC
 SG_ S2P_Cfg5_CellSeries_Num_05 : 16|12@1+ (1,0) [0|4095] ""  PC
 SG_ S2P_Cfg5_Temps_Num_05 : 28|4@1+ (1,0) [0|15] ""  PC
 SG_ S2P_Cfg5_CSCs_Num_05 : 32|8@1+ (1,0) [0|255] ""  PC
 SG_ S2P_Cfg5_Utank_Norminal_05 : 40|16@1+ (0.1,0) [0|6553.5] "V"  PC
 SG_ S2P_Cfg5_CSCType_05 : 56|4@1+ (1,0) [0|15] ""  PC

BO_ 2416373318 S2P_Cfg5__06: 8 SBMU
 SG_ S2P_Cfg5_SBMU_Add_06 : 0|8@1+ (1,0) [0|255] ""  PC
 SG_ S2P_Cfg5_ModuleParal_Num_06 : 8|8@1+ (1,0) [0|255] ""  PC
 SG_ S2P_Cfg5_CellSeries_Num_06 : 16|12@1+ (1,0) [0|4095] ""  PC
 SG_ S2P_Cfg5_Temps_Num_06 : 28|4@1+ (1,0) [0|15] ""  PC
 SG_ S2P_Cfg5_CSCs_Num_06 : 32|8@1+ (1,0) [0|255] ""  PC
 SG_ S2P_Cfg5_Utank_Norminal_06 : 40|16@1+ (0.1,0) [0|6553.5] "V"  PC
 SG_ S2P_Cfg5_CSCType_06 : 56|4@1+ (1,0) [0|15] ""  PC

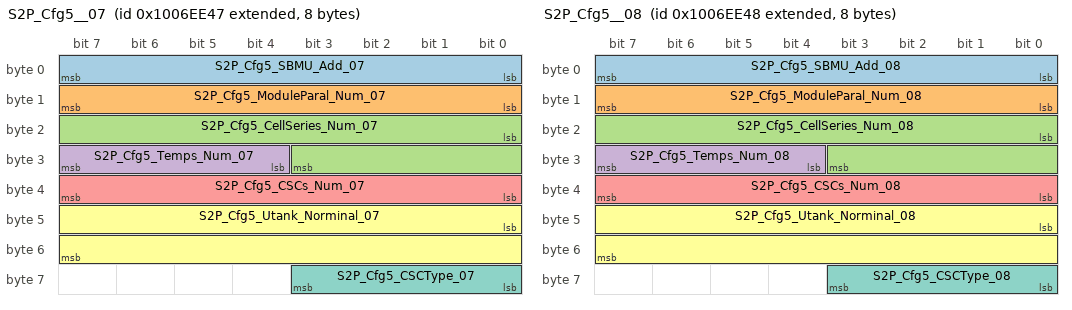
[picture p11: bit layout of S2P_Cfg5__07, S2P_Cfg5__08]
BO_ 2416373319 S2P_Cfg5__07: 8 SBMU
 SG_ S2P_Cfg5_SBMU_Add_07 : 0|8@1+ (1,0) [0|255] ""  PC
 SG_ S2P_Cfg5_ModuleParal_Num_07 : 8|8@1+ (1,0) [0|255] ""  PC
 SG_ S2P_Cfg5_CellSeries_Num_07 : 16|12@1+ (1,0) [0|4095] ""  PC
 SG_ S2P_Cfg5_Temps_Num_07 : 28|4@1+ (1,0) [0|15] ""  PC
 SG_ S2P_Cfg5_CSCs_Num_07 : 32|8@1+ (1,0) [0|255] ""  PC
 SG_ S2P_Cfg5_Utank_Norminal_07 : 40|16@1+ (0.1,0) [0|6553.5] "V"  PC
 SG_ S2P_Cfg5_CSCType_07 : 56|4@1+ (1,0) [0|15] ""  PC

BO_ 2416373320 S2P_Cfg5__08: 8 SBMU
 SG_ S2P_Cfg5_SBMU_Add_08 : 0|8@1+ (1,0) [0|255] ""  PC
 SG_ S2P_Cfg5_ModuleParal_Num_08 : 8|8@1+ (1,0) [0|255] ""  PC
 SG_ S2P_Cfg5_CellSeries_Num_08 : 16|12@1+ (1,0) [0|4095] ""  PC
 SG_ S2P_Cfg5_Temps_Num_08 : 28|4@1+ (1,0) [0|15] ""  PC
 SG_ S2P_Cfg5_CSCs_Num_08 : 32|8@1+ (1,0) [0|255] ""  PC
 SG_ S2P_Cfg5_Utank_Norminal_08 : 40|16@1+ (0.1,0) [0|6553.5] "V"  PC
 SG_ S2P_Cfg5_CSCType_08 : 56|4@1+ (1,0) [0|15] ""  PC

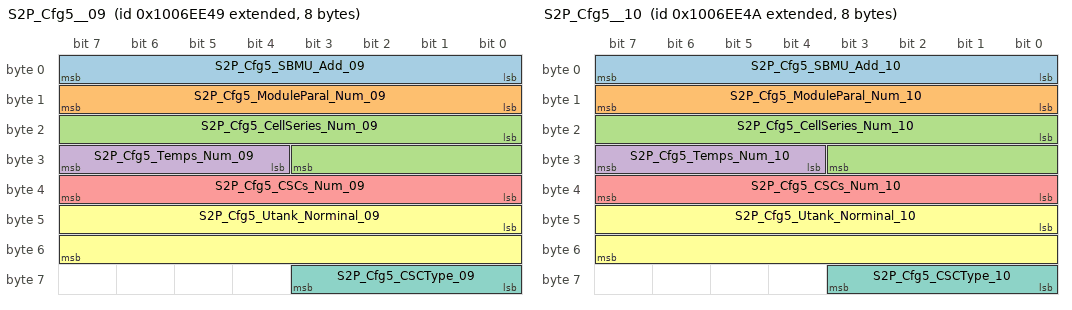
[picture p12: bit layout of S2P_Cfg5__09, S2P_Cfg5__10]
BO_ 2416373321 S2P_Cfg5__09: 8 SBMU
 SG_ S2P_Cfg5_SBMU_Add_09 : 0|8@1+ (1,0) [0|255] ""  PC
 SG_ S2P_Cfg5_ModuleParal_Num_09 : 8|8@1+ (1,0) [0|255] ""  PC
 SG_ S2P_Cfg5_CellSeries_Num_09 : 16|12@1+ (1,0) [0|4095] ""  PC
 SG_ S2P_Cfg5_Temps_Num_09 : 28|4@1+ (1,0) [0|15] ""  PC
 SG_ S2P_Cfg5_CSCs_Num_09 : 32|8@1+ (1,0) [0|255] ""  PC
 SG_ S2P_Cfg5_Utank_Norminal_09 : 40|16@1+ (0.1,0) [0|6553.5] "V"  PC
 SG_ S2P_Cfg5_CSCType_09 : 56|4@1+ (1,0) [0|15] ""  PC

BO_ 2416373322 S2P_Cfg5__10: 8 SBMU
 SG_ S2P_Cfg5_SBMU_Add_10 : 0|8@1+ (1,0) [0|255] ""  PC
 SG_ S2P_Cfg5_ModuleParal_Num_10 : 8|8@1+ (1,0) [0|255] ""  PC
 SG_ S2P_Cfg5_CellSeries_Num_10 : 16|12@1+ (1,0) [0|4095] ""  PC
 SG_ S2P_Cfg5_Temps_Num_10 : 28|4@1+ (1,0) [0|15] ""  PC
 SG_ S2P_Cfg5_CSCs_Num_10 : 32|8@1+ (1,0) [0|255] ""  PC
 SG_ S2P_Cfg5_Utank_Norminal_10 : 40|16@1+ (0.1,0) [0|6553.5] "V"  PC
 SG_ S2P_Cfg5_CSCType_10 : 56|4@1+ (1,0) [0|15] ""  PC

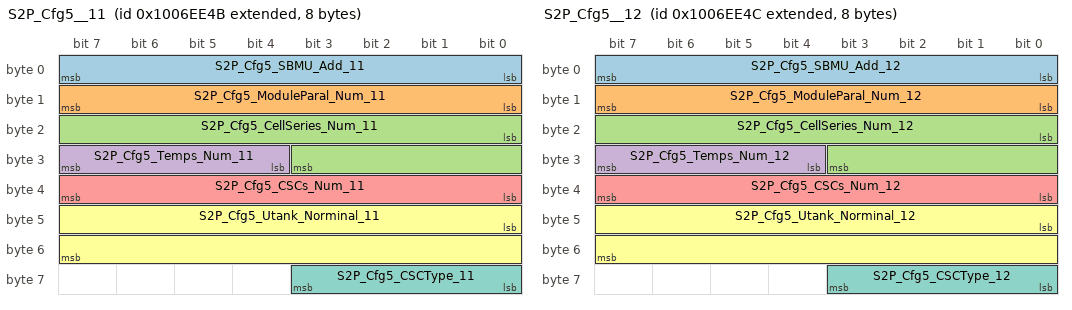
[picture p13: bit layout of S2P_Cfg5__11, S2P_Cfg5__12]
BO_ 2416373323 S2P_Cfg5__11: 8 SBMU
 SG_ S2P_Cfg5_SBMU_Add_11 : 0|8@1+ (1,0) [0|255] ""  PC
 SG_ S2P_Cfg5_ModuleParal_Num_11 : 8|8@1+ (1,0) [0|255] ""  PC
 SG_ S2P_Cfg5_CellSeries_Num_11 : 16|12@1+ (1,0) [0|4095] ""  PC
 SG_ S2P_Cfg5_Temps_Num_11 : 28|4@1+ (1,0) [0|15] ""  PC
 SG_ S2P_Cfg5_CSCs_Num_11 : 32|8@1+ (1,0) [0|255] ""  PC
 SG_ S2P_Cfg5_Utank_Norminal_11 : 40|16@1+ (0.1,0) [0|6553.5] "V"  PC
 SG_ S2P_Cfg5_CSCType_11 : 56|4@1+ (1,0) [0|15] ""  PC

BO_ 2416373324 S2P_Cfg5__12: 8 SBMU
 SG_ S2P_Cfg5_SBMU_Add_12 : 0|8@1+ (1,0) [0|255] ""  PC
 SG_ S2P_Cfg5_ModuleParal_Num_12 : 8|8@1+ (1,0) [0|255] ""  PC
 SG_ S2P_Cfg5_CellSeries_Num_12 : 16|12@1+ (1,0) [0|4095] ""  PC
 SG_ S2P_Cfg5_Temps_Num_12 : 28|4@1+ (1,0) [0|15] ""  PC
 SG_ S2P_Cfg5_CSCs_Num_12 : 32|8@1+ (1,0) [0|255] ""  PC
 SG_ S2P_Cfg5_Utank_Norminal_12 : 40|16@1+ (0.1,0) [0|6553.5] "V"  PC
 SG_ S2P_Cfg5_CSCType_12 : 56|4@1+ (1,0) [0|15] ""  PC

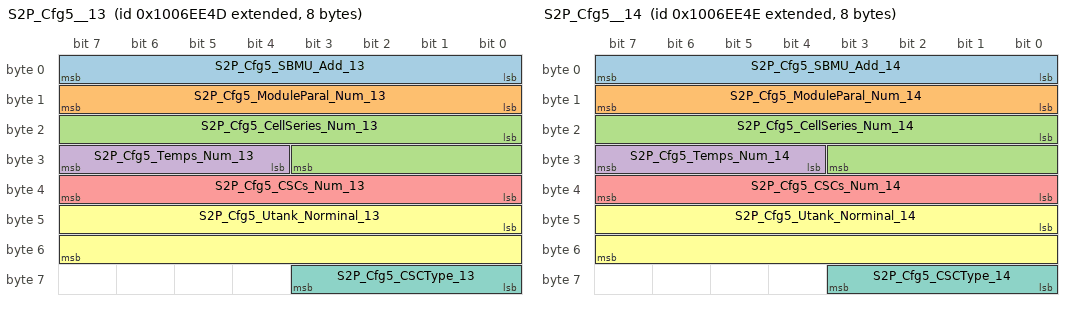
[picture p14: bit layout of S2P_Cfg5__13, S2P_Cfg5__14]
BO_ 2416373325 S2P_Cfg5__13: 8 SBMU
 SG_ S2P_Cfg5_SBMU_Add_13 : 0|8@1+ (1,0) [0|255] ""  PC
 SG_ S2P_Cfg5_ModuleParal_Num_13 : 8|8@1+ (1,0) [0|255] ""  PC
 SG_ S2P_Cfg5_CellSeries_Num_13 : 16|12@1+ (1,0) [0|4095] ""  PC
 SG_ S2P_Cfg5_Temps_Num_13 : 28|4@1+ (1,0) [0|15] ""  PC
 SG_ S2P_Cfg5_CSCs_Num_13 : 32|8@1+ (1,0) [0|255] ""  PC
 SG_ S2P_Cfg5_Utank_Norminal_13 : 40|16@1+ (0.1,0) [0|6553.5] "V"  PC
 SG_ S2P_Cfg5_CSCType_13 : 56|4@1+ (1,0) [0|15] ""  PC

BO_ 2416373326 S2P_Cfg5__14: 8 SBMU
 SG_ S2P_Cfg5_SBMU_Add_14 : 0|8@1+ (1,0) [0|255] ""  PC
 SG_ S2P_Cfg5_ModuleParal_Num_14 : 8|8@1+ (1,0) [0|255] ""  PC
 SG_ S2P_Cfg5_CellSeries_Num_14 : 16|12@1+ (1,0) [0|4095] ""  PC
 SG_ S2P_Cfg5_Temps_Num_14 : 28|4@1+ (1,0) [0|15] ""  PC
 SG_ S2P_Cfg5_CSCs_Num_14 : 32|8@1+ (1,0) [0|255] ""  PC
 SG_ S2P_Cfg5_Utank_Norminal_14 : 40|16@1+ (0.1,0) [0|6553.5] "V"  PC
 SG_ S2P_Cfg5_CSCType_14 : 56|4@1+ (1,0) [0|15] ""  PC

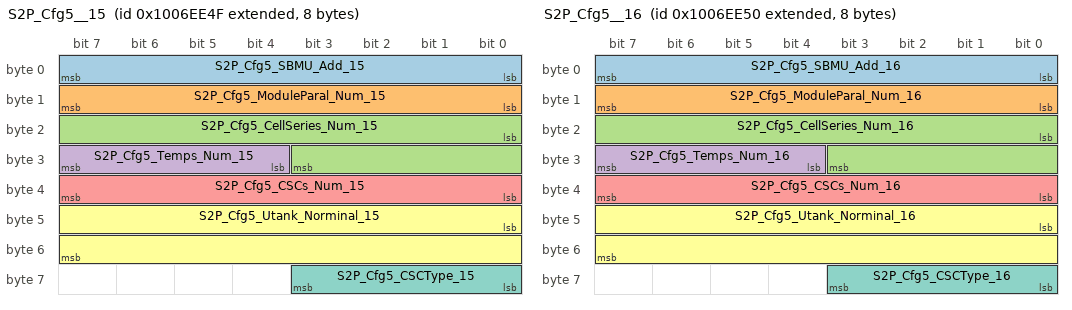
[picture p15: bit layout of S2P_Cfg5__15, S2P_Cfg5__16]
BO_ 2416373327 S2P_Cfg5__15: 8 SBMU
 SG_ S2P_Cfg5_SBMU_Add_15 : 0|8@1+ (1,0) [0|255] ""  PC
 SG_ S2P_Cfg5_ModuleParal_Num_15 : 8|8@1+ (1,0) [0|255] ""  PC
 SG_ S2P_Cfg5_CellSeries_Num_15 : 16|12@1+ (1,0) [0|4095] ""  PC
 SG_ S2P_Cfg5_Temps_Num_15 : 28|4@1+ (1,0) [0|15] ""  PC
 SG_ S2P_Cfg5_CSCs_Num_15 : 32|8@1+ (1,0) [0|255] ""  PC
 SG_ S2P_Cfg5_Utank_Norminal_15 : 40|16@1+ (0.1,0) [0|6553.5] "V"  PC
 SG_ S2P_Cfg5_CSCType_15 : 56|4@1+ (1,0) [0|15] ""  PC

BO_ 2416373328 S2P_Cfg5__16: 8 SBMU
 SG_ S2P_Cfg5_SBMU_Add_16 : 0|8@1+ (1,0) [0|255] ""  PC
 SG_ S2P_Cfg5_ModuleParal_Num_16 : 8|8@1+ (1,0) [0|255] ""  PC
 SG_ S2P_Cfg5_CellSeries_Num_16 : 16|12@1+ (1,0) [0|4095] ""  PC
 SG_ S2P_Cfg5_Temps_Num_16 : 28|4@1+ (1,0) [0|15] ""  PC
 SG_ S2P_Cfg5_CSCs_Num_16 : 32|8@1+ (1,0) [0|255] ""  PC
 SG_ S2P_Cfg5_Utank_Norminal_16 : 40|16@1+ (0.1,0) [0|6553.5] "V"  PC
 SG_ S2P_Cfg5_CSCType_16 : 56|4@1+ (1,0) [0|15] ""  PC

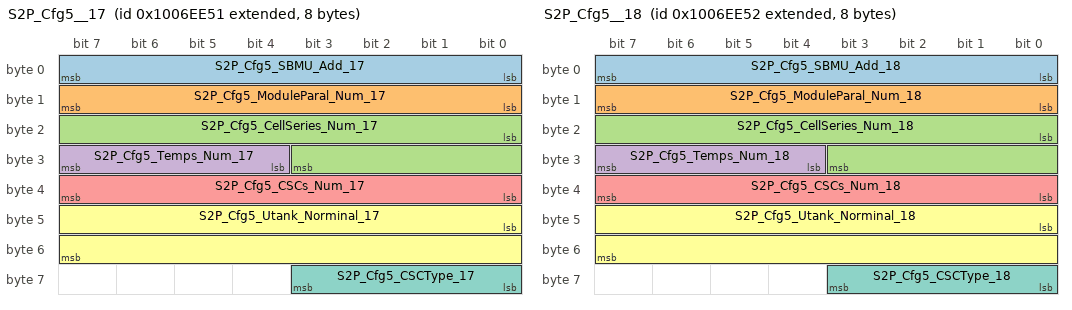
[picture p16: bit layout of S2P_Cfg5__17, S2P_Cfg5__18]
BO_ 2416373329 S2P_Cfg5__17: 8 SBMU
 SG_ S2P_Cfg5_SBMU_Add_17 : 0|8@1+ (1,0) [0|255] ""  PC
 SG_ S2P_Cfg5_ModuleParal_Num_17 : 8|8@1+ (1,0) [0|255] ""  PC
 SG_ S2P_Cfg5_CellSeries_Num_17 : 16|12@1+ (1,0) [0|4095] ""  PC
 SG_ S2P_Cfg5_Temps_Num_17 : 28|4@1+ (1,0) [0|15] ""  PC
 SG_ S2P_Cfg5_CSCs_Num_17 : 32|8@1+ (1,0) [0|255] ""  PC
 SG_ S2P_Cfg5_Utank_Norminal_17 : 40|16@1+ (0.1,0) [0|6553.5] "V"  PC
 SG_ S2P_Cfg5_CSCType_17 : 56|4@1+ (1,0) [0|15] ""  PC

BO_ 2416373330 S2P_Cfg5__18: 8 SBMU
 SG_ S2P_Cfg5_SBMU_Add_18 : 0|8@1+ (1,0) [0|255] ""  PC
 SG_ S2P_Cfg5_ModuleParal_Num_18 : 8|8@1+ (1,0) [0|255] ""  PC
 SG_ S2P_Cfg5_CellSeries_Num_18 : 16|12@1+ (1,0) [0|4095] ""  PC
 SG_ S2P_Cfg5_Temps_Num_18 : 28|4@1+ (1,0) [0|15] ""  PC
 SG_ S2P_Cfg5_CSCs_Num_18 : 32|8@1+ (1,0) [0|255] ""  PC
 SG_ S2P_Cfg5_Utank_Norminal_18 : 40|16@1+ (0.1,0) [0|6553.5] "V"  PC
 SG_ S2P_Cfg5_CSCType_18 : 56|4@1+ (1,0) [0|15] ""  PC

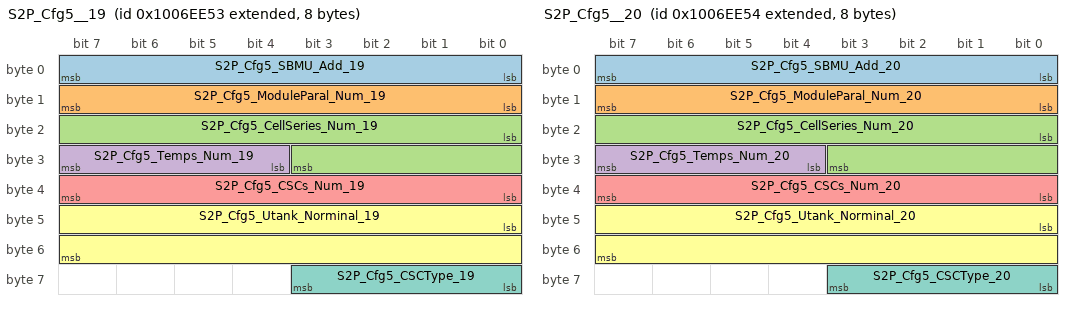
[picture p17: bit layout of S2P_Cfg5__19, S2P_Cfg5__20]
BO_ 2416373331 S2P_Cfg5__19: 8 SBMU
 SG_ S2P_Cfg5_SBMU_Add_19 : 0|8@1+ (1,0) [0|255] ""  PC
 SG_ S2P_Cfg5_ModuleParal_Num_19 : 8|8@1+ (1,0) [0|255] ""  PC
 SG_ S2P_Cfg5_CellSeries_Num_19 : 16|12@1+ (1,0) [0|4095] ""  PC
 SG_ S2P_Cfg5_Temps_Num_19 : 28|4@1+ (1,0) [0|15] ""  PC
 SG_ S2P_Cfg5_CSCs_Num_19 : 32|8@1+ (1,0) [0|255] ""  PC
 SG_ S2P_Cfg5_Utank_Norminal_19 : 40|16@1+ (0.1,0) [0|6553.5] "V"  PC
 SG_ S2P_Cfg5_CSCType_19 : 56|4@1+ (1,0) [0|15] ""  PC

BO_ 2416373332 S2P_Cfg5__20: 8 SBMU
 SG_ S2P_Cfg5_SBMU_Add_20 : 0|8@1+ (1,0) [0|255] ""  PC
 SG_ S2P_Cfg5_ModuleParal_Num_20 : 8|8@1+ (1,0) [0|255] ""  PC
 SG_ S2P_Cfg5_CellSeries_Num_20 : 16|12@1+ (1,0) [0|4095] ""  PC
 SG_ S2P_Cfg5_Temps_Num_20 : 28|4@1+ (1,0) [0|15] ""  PC
 SG_ S2P_Cfg5_CSCs_Num_20 : 32|8@1+ (1,0) [0|255] ""  PC
 SG_ S2P_Cfg5_Utank_Norminal_20 : 40|16@1+ (0.1,0) [0|6553.5] "V"  PC
 SG_ S2P_Cfg5_CSCType_20 : 56|4@1+ (1,0) [0|15] ""  PC

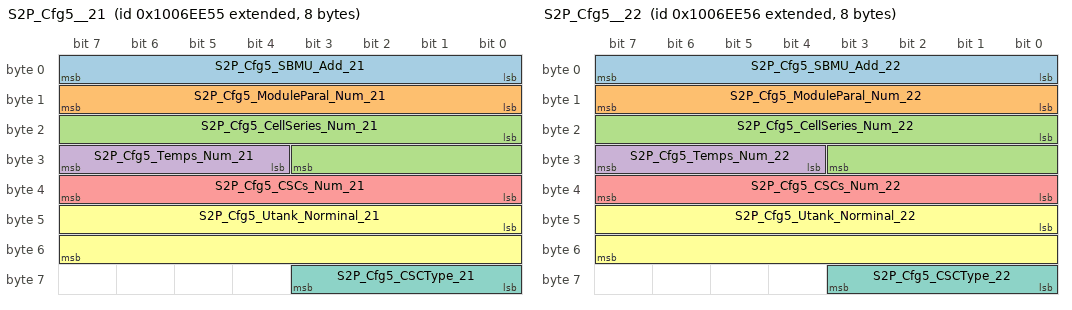
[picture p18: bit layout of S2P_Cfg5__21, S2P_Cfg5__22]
BO_ 2416373333 S2P_Cfg5__21: 8 SBMU
 SG_ S2P_Cfg5_SBMU_Add_21 : 0|8@1+ (1,0) [0|255] ""  PC
 SG_ S2P_Cfg5_ModuleParal_Num_21 : 8|8@1+ (1,0) [0|255] ""  PC
 SG_ S2P_Cfg5_CellSeries_Num_21 : 16|12@1+ (1,0) [0|4095] ""  PC
 SG_ S2P_Cfg5_Temps_Num_21 : 28|4@1+ (1,0) [0|15] ""  PC
 SG_ S2P_Cfg5_CSCs_Num_21 : 32|8@1+ (1,0) [0|255] ""  PC
 SG_ S2P_Cfg5_Utank_Norminal_21 : 40|16@1+ (0.1,0) [0|6553.5] "V"  PC
 SG_ S2P_Cfg5_CSCType_21 : 56|4@1+ (1,0) [0|15] ""  PC

BO_ 2416373334 S2P_Cfg5__22: 8 SBMU
 SG_ S2P_Cfg5_SBMU_Add_22 : 0|8@1+ (1,0) [0|255] ""  PC
 SG_ S2P_Cfg5_ModuleParal_Num_22 : 8|8@1+ (1,0) [0|255] ""  PC
 SG_ S2P_Cfg5_CellSeries_Num_22 : 16|12@1+ (1,0) [0|4095] ""  PC
 SG_ S2P_Cfg5_Temps_Num_22 : 28|4@1+ (1,0) [0|15] ""  PC
 SG_ S2P_Cfg5_CSCs_Num_22 : 32|8@1+ (1,0) [0|255] ""  PC
 SG_ S2P_Cfg5_Utank_Norminal_22 : 40|16@1+ (0.1,0) [0|6553.5] "V"  PC
 SG_ S2P_Cfg5_CSCType_22 : 56|4@1+ (1,0) [0|15] ""  PC

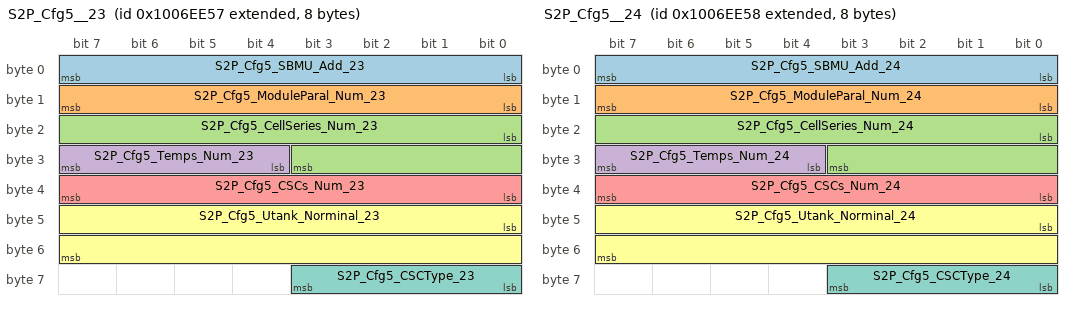
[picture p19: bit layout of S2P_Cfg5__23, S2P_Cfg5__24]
BO_ 2416373335 S2P_Cfg5__23: 8 SBMU
 SG_ S2P_Cfg5_SBMU_Add_23 : 0|8@1+ (1,0) [0|255] ""  PC
 SG_ S2P_Cfg5_ModuleParal_Num_23 : 8|8@1+ (1,0) [0|255] ""  PC
 SG_ S2P_Cfg5_CellSeries_Num_23 : 16|12@1+ (1,0) [0|4095] ""  PC
 SG_ S2P_Cfg5_Temps_Num_23 : 28|4@1+ (1,0) [0|15] ""  PC
 SG_ S2P_Cfg5_CSCs_Num_23 : 32|8@1+ (1,0) [0|255] ""  PC
 SG_ S2P_Cfg5_Utank_Norminal_23 : 40|16@1+ (0.1,0) [0|6553.5] "V"  PC
 SG_ S2P_Cfg5_CSCType_23 : 56|4@1+ (1,0) [0|15] ""  PC

BO_ 2416373336 S2P_Cfg5__24: 8 SBMU
 SG_ S2P_Cfg5_SBMU_Add_24 : 0|8@1+ (1,0) [0|255] ""  PC
 SG_ S2P_Cfg5_ModuleParal_Num_24 : 8|8@1+ (1,0) [0|255] ""  PC
 SG_ S2P_Cfg5_CellSeries_Num_24 : 16|12@1+ (1,0) [0|4095] ""  PC
 SG_ S2P_Cfg5_Temps_Num_24 : 28|4@1+ (1,0) [0|15] ""  PC
 SG_ S2P_Cfg5_CSCs_Num_24 : 32|8@1+ (1,0) [0|255] ""  PC
 SG_ S2P_Cfg5_Utank_Norminal_24 : 40|16@1+ (0.1,0) [0|6553.5] "V"  PC
 SG_ S2P_Cfg5_CSCType_24 : 56|4@1+ (1,0) [0|15] ""  PC

CM_ SG_ 2416176750 S2P_Cfg2_SW_Ver_Byte9_46 "SBMU软件版本号Byte9对应的ASCII码";
CM_ SG_ 2416176750 S2P_Cfg2_SW_Ver_Byte10_46 "SBMU软件版本号Byte10对应的ASCII码";
CM_ SG_ 2416176750 S2P_Cfg2_SW_Ver_Byte11_46 "SBMU软件版本号Byte11对应的ASCII码";
CM_ SG_ 2416176750 S2P_Cfg2_SW_Ver_Byte12_46 "SBMU软件版本号Byte12对应的ASCII码";
CM_ SG_ 2416176750 S2P_Cfg2_SW_Ver_Byte13_46 "SBMU软件版本号Byte13对应的ASCII码";
CM_ SG_ 2416176750 S2P_Cfg2_SW_Ver_Byte14_46 "SBMU软件版本号Byte14对应的ASCII码";
CM_ SG_ 2416176750 S2P_Cfg2_SW_Ver_Byte15_46 "SBMU软件版本号Byte15对应的ASCII码";
CM_ SG_ 2416176750 S2P_Cfg2_SW_Ver_Byte16_46 "SBMU软件版本号最高字节Byte16对应的ASCII码";
CM_ SG_ 2416176751 S2P_Cfg2_SW_Ver_Byte9_47 "SBMU软件版本号Byte9对应的ASCII码";
CM_ SG_ 2416176751 S2P_Cfg2_SW_Ver_Byte10_47 "SBMU软件版本号Byte10对应的ASCII码";
CM_ SG_ 2416176751 S2P_Cfg2_SW_Ver_Byte11_47 "SBMU软件版本号Byte11对应的ASCII码";
CM_ SG_ 2416176751 S2P_Cfg2_SW_Ver_Byte12_47 "SBMU软件版本号Byte12对应的ASCII码";
CM_ SG_ 2416176751 S2P_Cfg2_SW_Ver_Byte13_47 "SBMU软件版本号Byte13对应的ASCII码";
CM_ SG_ 2416176751 S2P_Cfg2_SW_Ver_Byte14_47 "SBMU软件版本号Byte14对应的ASCII码";
CM_ SG_ 2416176751 S2P_Cfg2_SW_Ver_Byte15_47 "SBMU软件版本号Byte15对应的ASCII码";
CM_ SG_ 2416176751 S2P_Cfg2_SW_Ver_Byte16_47 "SBMU软件版本号最高字节Byte16对应的ASCII码";
CM_ SG_ 2416176752 S2P_Cfg2_SW_Ver_Byte9_48 "SBMU软件版本号Byte9对应的ASCII码";
CM_ SG_ 2416176752 S2P_Cfg2_SW_Ver_Byte10_48 "SBMU软件版本号Byte10对应的ASCII码";
CM_ SG_ 2416176752 S2P_Cfg2_SW_Ver_Byte11_48 "SBMU软件版本号Byte11对应的ASCII码";
CM_ SG_ 2416176752 S2P_Cfg2_SW_Ver_Byte12_48 "SBMU软件版本号Byte12对应的ASCII码";
CM_ SG_ 2416176752 S2P_Cfg2_SW_Ver_Byte13_48 "SBMU软件版本号Byte13对应的ASCII码";
CM_ SG_ 2416176752 S2P_Cfg2_SW_Ver_Byte14_48 "SBMU软件版本号Byte14对应的ASCII码";
CM_ SG_ 2416176752 S2P_Cfg2_SW_Ver_Byte15_48 "SBMU软件版本号Byte15对应的ASCII码";
CM_ SG_ 2416176752 S2P_Cfg2_SW_Ver_Byte16_48 "SBMU软件版本号最高字节Byte16对应的ASCII码";
CM_ SG_ 2416176753 S2P_Cfg2_SW_Ver_Byte9_49 "SBMU软件版本号Byte9对应的ASCII码";
CM_ SG_ 2416176753 S2P_Cfg2_SW_Ver_Byte10_49 "SBMU软件版本号Byte10对应的ASCII码";
CM_ SG_ 2416176753 S2P_Cfg2_SW_Ver_Byte11_49 "SBMU软件版本号Byte11对应的ASCII码";
CM_ SG_ 2416176753 S2P_Cfg2_SW_Ver_Byte12_49 "SBMU软件版本号Byte12对应的ASCII码";
CM_ SG_ 2416176753 S2P_Cfg2_SW_Ver_Byte13_49 "SBMU软件版本号Byte13对应的ASCII码";
CM_ SG_ 2416176753 S2P_Cfg2_SW_Ver_Byte14_49 "SBMU软件版本号Byte14对应的ASCII码";
CM_ SG_ 2416176753 S2P_Cfg2_SW_Ver_Byte15_49 "SBMU软件版本号Byte15对应的ASCII码";
CM_ SG_ 2416176753 S2P_Cfg2_SW_Ver_Byte16_49 "SBMU软件版本号最高字节Byte16对应的ASCII码";
CM_ SG_ 2416176754 S2P_Cfg2_SW_Ver_Byte9_50 "SBMU软件版本号Byte9对应的ASCII码";
CM_ SG_ 2416176754 S2P_Cfg2_SW_Ver_Byte10_50 "SBMU软件版本号Byte10对应的ASCII码";
CM_ SG_ 2416176754 S2P_Cfg2_SW_Ver_Byte11_50 "SBMU软件版本号Byte11对应的ASCII码";
CM_ SG_ 2416176754 S2P_Cfg2_SW_Ver_Byte12_50 "SBMU软件版本号Byte12对应的ASCII码";
CM_ SG_ 2416176754 S2P_Cfg2_SW_Ver_Byte13_50 "SBMU软件版本号Byte13对应的ASCII码";
CM_ SG_ 2416176754 S2P_Cfg2_SW_Ver_Byte14_50 "SBMU软件版本号Byte14对应的ASCII码";
CM_ SG_ 2416176754 S2P_Cfg2_SW_Ver_Byte15_50 "SBMU软件版本号Byte15对应的ASCII码";
CM_ SG_ 2416176754 S2P_Cfg2_SW_Ver_Byte16_50 "SBMU软件版本号最高字节Byte16对应的ASCII码";
CM_ SG_ 2416176755 S2P_Cfg2_SW_Ver_Byte9_51 "SBMU软件版本号Byte9对应的ASCII码";
CM_ SG_ 2416176755 S2P_Cfg2_SW_Ver_Byte10_51 "SBMU软件版本号Byte10对应的ASCII码";
CM_ SG_ 2416176755 S2P_Cfg2_SW_Ver_Byte11_51 "SBMU软件版本号Byte11对应的ASCII码";
CM_ SG_ 2416176755 S2P_Cfg2_SW_Ver_Byte12_51 "SBMU软件版本号Byte12对应的ASCII码";
CM_ SG_ 2416176755 S2P_Cfg2_SW_Ver_Byte13_51 "SBMU软件版本号Byte13对应的ASCII码";
CM_ SG_ 2416176755 S2P_Cfg2_SW_Ver_Byte14_51 "SBMU软件版本号Byte14对应的ASCII码";
CM_ SG_ 2416176755 S2P_Cfg2_SW_Ver_Byte15_51 "SBMU软件版本号Byte15对应的ASCII码";
CM_ SG_ 2416176755 S2P_Cfg2_SW_Ver_Byte16_51 "SBMU软件版本号最高字节Byte16对应的ASCII码";
CM_ SG_ 2416176756 S2P_Cfg2_SW_Ver_Byte9_52 "SBMU软件版本号Byte9对应的ASCII码";
CM_ SG_ 2416176756 S2P_Cfg2_SW_Ver_Byte10_52 "SBMU软件版本号Byte10对应的ASCII码";
CM_ SG_ 2416176756 S2P_Cfg2_SW_Ver_Byte11_52 "SBMU软件版本号Byte11对应的ASCII码";
CM_ SG_ 2416176756 S2P_Cfg2_SW_Ver_Byte12_52 "SBMU软件版本号Byte12对应的ASCII码";
CM_ SG_ 2416176756 S2P_Cfg2_SW_Ver_Byte13_52 "SBMU软件版本号Byte13对应的ASCII码";
CM_ SG_ 2416176756 S2P_Cfg2_SW_Ver_Byte14_52 "SBMU软件版本号Byte14对应的ASCII码";
CM_ SG_ 2416176756 S2P_Cfg2_SW_Ver_Byte15_52 "SBMU软件版本号Byte15对应的ASCII码";
CM_ SG_ 2416176756 S2P_Cfg2_SW_Ver_Byte16_52 "SBMU软件版本号最高字节Byte16对应的ASCII码";
CM_ SG_ 2416176757 S2P_Cfg2_SW_Ver_Byte9_53 "SBMU软件版本号Byte9对应的ASCII码";
CM_ SG_ 2416176757 S2P_Cfg2_SW_Ver_Byte10_53 "SBMU软件版本号Byte10对应的ASCII码";
CM_ SG_ 2416176757 S2P_Cfg2_SW_Ver_Byte11_53 "SBMU软件版本号Byte11对应的ASCII码";
CM_ SG_ 2416176757 S2P_Cfg2_SW_Ver_Byte12_53 "SBMU软件版本号Byte12对应的ASCII码";
CM_ SG_ 2416176757 S2P_Cfg2_SW_Ver_Byte13_53 "SBMU软件版本号Byte13对应的ASCII码";
CM_ SG_ 2416176757 S2P_Cfg2_SW_Ver_Byte14_53 "SBMU软件版本号Byte14对应的ASCII码";
CM_ SG_ 2416176757 S2P_Cfg2_SW_Ver_Byte15_53 "SBMU软件版本号Byte15对应的ASCII码";
CM_ SG_ 2416176757 S2P_Cfg2_SW_Ver_Byte16_53 "SBMU软件版本号最高字节Byte16对应的ASCII码";
CM_ SG_ 2416176758 S2P_Cfg2_SW_Ver_Byte9_54 "SBMU软件版本号Byte9对应的ASCII码";
CM_ SG_ 2416176758 S2P_Cfg2_SW_Ver_Byte10_54 "SBMU软件版本号Byte10对应的ASCII码";
CM_ SG_ 2416176758 S2P_Cfg2_SW_Ver_Byte11_54 "SBMU软件版本号Byte11对应的ASCII码";
CM_ SG_ 2416176758 S2P_Cfg2_SW_Ver_Byte12_54 "SBMU软件版本号Byte12对应的ASCII码";
CM_ SG_ 2416176758 S2P_Cfg2_SW_Ver_Byte13_54 "SBMU软件版本号Byte13对应的ASCII码";
CM_ SG_ 2416176758 S2P_Cfg2_SW_Ver_Byte14_54 "SBMU软件版本号Byte14对应的ASCII码";
CM_ SG_ 2416176758 S2P_Cfg2_SW_Ver_Byte15_54 "SBMU软件版本号Byte15对应的ASCII码";
CM_ SG_ 2416176758 S2P_Cfg2_SW_Ver_Byte16_54 "SBMU软件版本号最高字节Byte16对应的ASCII码";
CM_ SG_ 2416176759 S2P_Cfg2_SW_Ver_Byte9_55 "SBMU软件版本号Byte9对应的ASCII码";
CM_ SG_ 2416176759 S2P_Cfg2_SW_Ver_Byte10_55 "SBMU软件版本号Byte10对应的ASCII码";
CM_ SG_ 2416176759 S2P_Cfg2_SW_Ver_Byte11_55 "SBMU软件版本号Byte11对应的ASCII码";
CM_ SG_ 2416176759 S2P_Cfg2_SW_Ver_Byte12_55 "SBMU软件版本号Byte12对应的ASCII码";
CM_ SG_ 2416176759 S2P_Cfg2_SW_Ver_Byte13_55 "SBMU软件版本号Byte13对应的ASCII码";
CM_ SG_ 2416176759 S2P_Cfg2_SW_Ver_Byte14_55 "SBMU软件版本号Byte14对应的ASCII码";
CM_ SG_ 2416176759 S2P_Cfg2_SW_Ver_Byte15_55 "SBMU软件版本号Byte15对应的ASCII码";
CM_ SG_ 2416176759 S2P_Cfg2_SW_Ver_Byte16_55 "SBMU软件版本号最高字节Byte16对应的ASCII码";
CM_ SG_ 2416176760 S2P_Cfg2_SW_Ver_Byte9_56 "SBMU软件版本号Byte9对应的ASCII码";
CM_ SG_ 2416176760 S2P_Cfg2_SW_Ver_Byte10_56 "SBMU软件版本号Byte10对应的ASCII码";
CM_ SG_ 2416176760 S2P_Cfg2_SW_Ver_Byte11_56 "SBMU软件版本号Byte11对应的ASCII码";
CM_ SG_ 2416176760 S2P_Cfg2_SW_Ver_Byte12_56 "SBMU软件版本号Byte12对应的ASCII码";
CM_ SG_ 2416176760 S2P_Cfg2_SW_Ver_Byte13_56 "SBMU软件版本号Byte13对应的ASCII码";
CM_ SG_ 2416176760 S2P_Cfg2_SW_Ver_Byte14_56 "SBMU软件版本号Byte14对应的ASCII码";
CM_ SG_ 2416176760 S2P_Cfg2_SW_Ver_Byte15_56 "SBMU软件版本号Byte15对应的ASCII码";
CM_ SG_ 2416176760 S2P_Cfg2_SW_Ver_Byte16_56 "SBMU软件版本号最高字节Byte16对应的ASCII码";
CM_ SG_ 2416176761 S2P_Cfg2_SW_Ver_Byte9_57 "SBMU软件版本号Byte9对应的ASCII码";
CM_ SG_ 2416176761 S2P_Cfg2_SW_Ver_Byte10_57 "SBMU软件版本号Byte10对应的ASCII码";
CM_ SG_ 2416176761 S2P_Cfg2_SW_Ver_Byte11_57 "SBMU软件版本号Byte11对应的ASCII码";
CM_ SG_ 2416176761 S2P_Cfg2_SW_Ver_Byte12_57 "SBMU软件版本号Byte12对应的ASCII码";
CM_ SG_ 2416176761 S2P_Cfg2_SW_Ver_Byte13_57 "SBMU软件版本号Byte13对应的ASCII码";
CM_ SG_ 2416176761 S2P_Cfg2_SW_Ver_Byte14_57 "SBMU软件版本号Byte14对应的ASCII码";
CM_ SG_ 2416176761 S2P_Cfg2_SW_Ver_Byte15_57 "SBMU软件版本号Byte15对应的ASCII码";
CM_ SG_ 2416176761 S2P_Cfg2_SW_Ver_Byte16_57 "SBMU软件版本号最高字节Byte16对应的ASCII码";
CM_ SG_ 2416176762 S2P_Cfg2_SW_Ver_Byte9_58 "SBMU软件版本号Byte9对应的ASCII码";
CM_ SG_ 2416176762 S2P_Cfg2_SW_Ver_Byte10_58 "SBMU软件版本号Byte10对应的ASCII码";
CM_ SG_ 2416176762 S2P_Cfg2_SW_Ver_Byte11_58 "SBMU软件版本号Byte11对应的ASCII码";
CM_ SG_ 2416176762 S2P_Cfg2_SW_Ver_Byte12_58 "SBMU软件版本号Byte12对应的ASCII码";
CM_ SG_ 2416176762 S2P_Cfg2_SW_Ver_Byte13_58 "SBMU软件版本号Byte13对应的ASCII码";
CM_ SG_ 2416176762 S2P_Cfg2_SW_Ver_Byte14_58 "SBMU软件版本号Byte14对应的ASCII码";
CM_ SG_ 2416176762 S2P_Cfg2_SW_Ver_Byte15_58 "SBMU软件版本号Byte15对应的ASCII码";
CM_ SG_ 2416176762 S2P_Cfg2_SW_Ver_Byte16_58 "SBMU软件版本号最高字节Byte16对应的ASCII码";
CM_ SG_ 2416176763 S2P_Cfg2_SW_Ver_Byte9_59 "SBMU软件版本号Byte9对应的ASCII码";
CM_ SG_ 2416176763 S2P_Cfg2_SW_Ver_Byte10_59 "SBMU软件版本号Byte10对应的ASCII码";
CM_ SG_ 2416176763 S2P_Cfg2_SW_Ver_Byte11_59 "SBMU软件版本号Byte11对应的ASCII码";
CM_ SG_ 2416176763 S2P_Cfg2_SW_Ver_Byte12_59 "SBMU软件版本号Byte12对应的ASCII码";
CM_ SG_ 2416176763 S2P_Cfg2_SW_Ver_Byte13_59 "SBMU软件版本号Byte13对应的ASCII码";
CM_ SG_ 2416176763 S2P_Cfg2_SW_Ver_Byte14_59 "SBMU软件版本号Byte14对应的ASCII码";
CM_ SG_ 2416176763 S2P_Cfg2_SW_Ver_Byte15_59 "SBMU软件版本号Byte15对应的ASCII码";
CM_ SG_ 2416176763 S2P_Cfg2_SW_Ver_Byte16_59 "SBMU软件版本号最高字节Byte16对应的ASCII码";
CM_ SG_ 2416176764 S2P_Cfg2_SW_Ver_Byte9_60 "SBMU软件版本号Byte9对应的ASCII码";
CM_ SG_ 2416176764 S2P_Cfg2_SW_Ver_Byte10_60 "SBMU软件版本号Byte10对应的ASCII码";
CM_ SG_ 2416176764 S2P_Cfg2_SW_Ver_Byte11_60 "SBMU软件版本号Byte11对应的ASCII码";
CM_ SG_ 2416176764 S2P_Cfg2_SW_Ver_Byte12_60 "SBMU软件版本号Byte12对应的ASCII码";
CM_ SG_ 2416176764 S2P_Cfg2_SW_Ver_Byte13_60 "SBMU软件版本号Byte13对应的ASCII码";
CM_ SG_ 2416176764 S2P_Cfg2_SW_Ver_Byte14_60 "SBMU软件版本号Byte14对应的ASCII码";
CM_ SG_ 2416176764 S2P_Cfg2_SW_Ver_Byte15_60 "SBMU软件版本号Byte15对应的ASCII码";
CM_ SG_ 2416176764 S2P_Cfg2_SW_Ver_Byte16_60 "SBMU软件版本号最高字节Byte16对应的ASCII码";
CM_ SG_ 2416176765 S2P_Cfg2_SW_Ver_Byte9_61 "SBMU软件版本号Byte9对应的ASCII码";
CM_ SG_ 2416176765 S2P_Cfg2_SW_Ver_Byte10_61 "SBMU软件版本号Byte10对应的ASCII码";
CM_ SG_ 2416176765 S2P_Cfg2_SW_Ver_Byte11_61 "SBMU软件版本号Byte11对应的ASCII码";
CM_ SG_ 2416176765 S2P_Cfg2_SW_Ver_Byte12_61 "SBMU软件版本号Byte12对应的ASCII码";
CM_ SG_ 2416176765 S2P_Cfg2_SW_Ver_Byte13_61 "SBMU软件版本号Byte13对应的ASCII码";
CM_ SG_ 2416176765 S2P_Cfg2_SW_Ver_Byte14_61 "SBMU软件版本号Byte14对应的ASCII码";
CM_ SG_ 2416176765 S2P_Cfg2_SW_Ver_Byte15_61 "SBMU软件版本号Byte15对应的ASCII码";
CM_ SG_ 2416176765 S2P_Cfg2_SW_Ver_Byte16_61 "SBMU软件版本号最高字节Byte16对应的ASCII码";
CM_ SG_ 2416176766 S2P_Cfg2_SW_Ver_Byte9_62 "SBMU软件版本号Byte9对应的ASCII码";
CM_ SG_ 2416176766 S2P_Cfg2_SW_Ver_Byte10_62 "SBMU软件版本号Byte10对应的ASCII码";
CM_ SG_ 2416176766 S2P_Cfg2_SW_Ver_Byte11_62 "SBMU软件版本号Byte11对应的ASCII码";
CM_ SG_ 2416176766 S2P_Cfg2_SW_Ver_Byte12_62 "SBMU软件版本号Byte12对应的ASCII码";
CM_ SG_ 2416176766 S2P_Cfg2_SW_Ver_Byte13_62 "SBMU软件版本号Byte13对应的ASCII码";
CM_ SG_ 2416176766 S2P_Cfg2_SW_Ver_Byte14_62 "SBMU软件版本号Byte14对应的ASCII码";
CM_ SG_ 2416176766 S2P_Cfg2_SW_Ver_Byte15_62 "SBMU软件版本号Byte15对应的ASCII码";
CM_ SG_ 2416176766 S2P_Cfg2_SW_Ver_Byte16_62 "SBMU软件版本号最高字节Byte16对应的ASCII码";
CM_ SG_ 2416176767 S2P_Cfg2_SW_Ver_Byte9_63 "SBMU软件版本号Byte9对应的ASCII码";
CM_ SG_ 2416176767 S2P_Cfg2_SW_Ver_Byte10_63 "SBMU软件版本号Byte10对应的ASCII码";
CM_ SG_ 2416176767 S2P_Cfg2_SW_Ver_Byte11_63 "SBMU软件版本号Byte11对应的ASCII码";
CM_ SG_ 2416176767 S2P_Cfg2_SW_Ver_Byte12_63 "SBMU软件版本号Byte12对应的ASCII码";
CM_ SG_ 2416176767 S2P_Cfg2_SW_Ver_Byte13_63 "SBMU软件版本号Byte13对应的ASCII码";
CM_ SG_ 2416176767 S2P_Cfg2_SW_Ver_Byte14_63 "SBMU软件版本号Byte14对应的ASCII码";
CM_ SG_ 2416176767 S2P_Cfg2_SW_Ver_Byte15_63 "SBMU软件版本号Byte15对应的ASCII码";
CM_ SG_ 2416176767 S2P_Cfg2_SW_Ver_Byte16_63 "SBMU软件版本号最高字节Byte16对应的ASCII码";
CM_ SG_ 2416242241 S2P_Cfg3_HW_Ver_Byte1_01 "SBMU硬件版本号最低字节Byte1对应的ASCII码";
CM_ SG_ 2416242241 S2P_Cfg3_HW_Ver_Byte2_01 "SBMU硬件版本号Byte2对应的ASCII码";
CM_ SG_ 2416242241 S2P_Cfg3_HW_Ver_Byte3_01 "SBMU硬件版本号Byte3对应的ASCII码";
CM_ SG_ 2416242241 S2P_Cfg3_HW_Ver_Byte4_01 "SBMU硬件版本号Byte4对应的ASCII码";
CM_ SG_ 2416242241 S2P_Cfg3_HW_Ver_Byte5_01 "SBMU硬件版本号Byte5对应的ASCII码";
CM_ SG_ 2416242241 S2P_Cfg3_HW_Ver_Byte6_01 "SBMU硬件版本号Byte6对应的ASCII码";
CM_ SG_ 2416242241 S2P_Cfg3_HW_Ver_Byte7_01 "SBMU硬件版本号Byte7对应的ASCII码";
CM_ SG_ 2416242241 S2P_Cfg3_HW_Ver_Byte8_01 "SBMU硬件版本号Byte8对应的ASCII码";
CM_ SG_ 2416242242 S2P_Cfg3_HW_Ver_Byte1_02 "SBMU硬件版本号最低字节Byte1对应的ASCII码";
CM_ SG_ 2416242242 S2P_Cfg3_HW_Ver_Byte2_02 "SBMU硬件版本号Byte2对应的ASCII码";
CM_ SG_ 2416242242 S2P_Cfg3_HW_Ver_Byte3_02 "SBMU硬件版本号Byte3对应的ASCII码";
CM_ SG_ 2416242242 S2P_Cfg3_HW_Ver_Byte4_02 "SBMU硬件版本号Byte4对应的ASCII码";
CM_ SG_ 2416242242 S2P_Cfg3_HW_Ver_Byte5_02 "SBMU硬件版本号Byte5对应的ASCII码";
CM_ SG_ 2416242242 S2P_Cfg3_HW_Ver_Byte6_02 "SBMU硬件版本号Byte6对应的ASCII码";
CM_ SG_ 2416242242 S2P_Cfg3_HW_Ver_Byte7_02 "SBMU硬件版本号Byte7对应的ASCII码";
CM_ SG_ 2416242242 S2P_Cfg3_HW_Ver_Byte8_02 "SBMU硬件版本号Byte8对应的ASCII码";
CM_ SG_ 2416242243 S2P_Cfg3_HW_Ver_Byte1_03 "SBMU硬件版本号最低字节Byte1对应的ASCII码";
CM_ SG_ 2416242243 S2P_Cfg3_HW_Ver_Byte2_03 "SBMU硬件版本号Byte2对应的ASCII码";
CM_ SG_ 2416242243 S2P_Cfg3_HW_Ver_Byte3_03 "SBMU硬件版本号Byte3对应的ASCII码";
CM_ SG_ 2416242243 S2P_Cfg3_HW_Ver_Byte4_03 "SBMU硬件版本号Byte4对应的ASCII码";
CM_ SG_ 2416242243 S2P_Cfg3_HW_Ver_Byte5_03 "SBMU硬件版本号Byte5对应的ASCII码";
CM_ SG_ 2416242243 S2P_Cfg3_HW_Ver_Byte6_03 "SBMU硬件版本号Byte6对应的ASCII码";
CM_ SG_ 2416242243 S2P_Cfg3_HW_Ver_Byte7_03 "SBMU硬件版本号Byte7对应的ASCII码";
CM_ SG_ 2416242243 S2P_Cfg3_HW_Ver_Byte8_03 "SBMU硬件版本号Byte8对应的ASCII码";
CM_ SG_ 2416242244 S2P_Cfg3_HW_Ver_Byte1_04 "SBMU硬件版本号最低字节Byte1对应的ASCII码";
CM_ SG_ 2416242244 S2P_Cfg3_HW_Ver_Byte2_04 "SBMU硬件版本号Byte2对应的ASCII码";
CM_ SG_ 2416242244 S2P_Cfg3_HW_Ver_Byte3_04 "SBMU硬件版本号Byte3对应的ASCII码";
CM_ SG_ 2416242244 S2P_Cfg3_HW_Ver_Byte4_04 "SBMU硬件版本号Byte4对应的ASCII码";
CM_ SG_ 2416242244 S2P_Cfg3_HW_Ver_Byte5_04 "SBMU硬件版本号Byte5对应的ASCII码";
CM_ SG_ 2416242244 S2P_Cfg3_HW_Ver_Byte6_04 "SBMU硬件版本号Byte6对应的ASCII码";
CM_ SG_ 2416242244 S2P_Cfg3_HW_Ver_Byte7_04 "SBMU硬件版本号Byte7对应的ASCII码";
CM_ SG_ 2416242244 S2P_Cfg3_HW_Ver_Byte8_04 "SBMU硬件版本号Byte8对应的ASCII码";
CM_ SG_ 2416242245 S2P_Cfg3_HW_Ver_Byte1_05 "SBMU硬件版本号最低字节Byte1对应的ASCII码";
CM_ SG_ 2416242245 S2P_Cfg3_HW_Ver_Byte2_05 "SBMU硬件版本号Byte2对应的ASCII码";
CM_ SG_ 2416242245 S2P_Cfg3_HW_Ver_Byte3_05 "SBMU硬件版本号Byte3对应的ASCII码";
CM_ SG_ 2416242245 S2P_Cfg3_HW_Ver_Byte4_05 "SBMU硬件版本号Byte4对应的ASCII码";
CM_ SG_ 2416242245 S2P_Cfg3_HW_Ver_Byte5_05 "SBMU硬件版本号Byte5对应的ASCII码";
CM_ SG_ 2416242245 S2P_Cfg3_HW_Ver_Byte6_05 "SBMU硬件版本号Byte6对应的ASCII码";
CM_ SG_ 2416242245 S2P_Cfg3_HW_Ver_Byte7_05 "SBMU硬件版本号Byte7对应的ASCII码";
CM_ SG_ 2416242245 S2P_Cfg3_HW_Ver_Byte8_05 "SBMU硬件版本号Byte8对应的ASCII码";
CM_ SG_ 2416242246 S2P_Cfg3_HW_Ver_Byte1_06 "SBMU硬件版本号最低字节Byte1对应的ASCII码";
CM_ SG_ 2416242246 S2P_Cfg3_HW_Ver_Byte2_06 "SBMU硬件版本号Byte2对应的ASCII码";
CM_ SG_ 2416242246 S2P_Cfg3_HW_Ver_Byte3_06 "SBMU硬件版本号Byte3对应的ASCII码";
CM_ SG_ 2416242246 S2P_Cfg3_HW_Ver_Byte4_06 "SBMU硬件版本号Byte4对应的ASCII码";
CM_ SG_ 2416242246 S2P_Cfg3_HW_Ver_Byte5_06 "SBMU硬件版本号Byte5对应的ASCII码";
CM_ SG_ 2416242246 S2P_Cfg3_HW_Ver_Byte6_06 "SBMU硬件版本号Byte6对应的ASCII码";
CM_ SG_ 2416242246 S2P_Cfg3_HW_Ver_Byte7_06 "SBMU硬件版本号Byte7对应的ASCII码";
CM_ SG_ 2416242246 S2P_Cfg3_HW_Ver_Byte8_06 "SBMU硬件版本号Byte8对应的ASCII码";
CM_ SG_ 2416242247 S2P_Cfg3_HW_Ver_Byte1_07 "SBMU硬件版本号最低字节Byte1对应的ASCII码";
CM_ SG_ 2416242247 S2P_Cfg3_HW_Ver_Byte2_07 "SBMU硬件版本号Byte2对应的ASCII码";
CM_ SG_ 2416242247 S2P_Cfg3_HW_Ver_Byte3_07 "SBMU硬件版本号Byte3对应的ASCII码";
CM_ SG_ 2416242247 S2P_Cfg3_HW_Ver_Byte4_07 "SBMU硬件版本号Byte4对应的ASCII码";
CM_ SG_ 2416242247 S2P_Cfg3_HW_Ver_Byte5_07 "SBMU硬件版本号Byte5对应的ASCII码";
CM_ SG_ 2416242247 S2P_Cfg3_HW_Ver_Byte6_07 "SBMU硬件版本号Byte6对应的ASCII码";
CM_ SG_ 2416242247 S2P_Cfg3_HW_Ver_Byte7_07 "SBMU硬件版本号Byte7对应的ASCII码";
CM_ SG_ 2416242247 S2P_Cfg3_HW_Ver_Byte8_07 "SBMU硬件版本号Byte8对应的ASCII码";
CM_ SG_ 2416242248 S2P_Cfg3_HW_Ver_Byte1_08 "SBMU硬件版本号最低字节Byte1对应的ASCII码";
CM_ SG_ 2416242248 S2P_Cfg3_HW_Ver_Byte2_08 "SBMU硬件版本号Byte2对应的ASCII码";
CM_ SG_ 2416242248 S2P_Cfg3_HW_Ver_Byte3_08 "SBMU硬件版本号Byte3对应的ASCII码";
CM_ SG_ 2416242248 S2P_Cfg3_HW_Ver_Byte4_08 "SBMU硬件版本号Byte4对应的ASCII码";
CM_ SG_ 2416242248 S2P_Cfg3_HW_Ver_Byte5_08 "SBMU硬件版本号Byte5对应的ASCII码";
CM_ SG_ 2416242248 S2P_Cfg3_HW_Ver_Byte6_08 "SBMU硬件版本号Byte6对应的ASCII码";
CM_ SG_ 2416242248 S2P_Cfg3_HW_Ver_Byte7_08 "SBMU硬件版本号Byte7对应的ASCII码";
CM_ SG_ 2416242248 S2P_Cfg3_HW_Ver_Byte8_08 "SBMU硬件版本号Byte8对应的ASCII码";
CM_ SG_ 2416242249 S2P_Cfg3_HW_Ver_Byte1_09 "SBMU硬件版本号最低字节Byte1对应的ASCII码";
CM_ SG_ 2416242249 S2P_Cfg3_HW_Ver_Byte2_09 "SBMU硬件版本号Byte2对应的ASCII码";
CM_ SG_ 2416242249 S2P_Cfg3_HW_Ver_Byte3_09 "SBMU硬件版本号Byte3对应的ASCII码";
CM_ SG_ 2416242249 S2P_Cfg3_HW_Ver_Byte4_09 "SBMU硬件版本号Byte4对应的ASCII码";
CM_ SG_ 2416242249 S2P_Cfg3_HW_Ver_Byte5_09 "SBMU硬件版本号Byte5对应的ASCII码";
CM_ SG_ 2416242249 S2P_Cfg3_HW_Ver_Byte6_09 "SBMU硬件版本号Byte6对应的ASCII码";
CM_ SG_ 2416242249 S2P_Cfg3_HW_Ver_Byte7_09 "SBMU硬件版本号Byte7对应的ASCII码";
CM_ SG_ 2416242249 S2P_Cfg3_HW_Ver_Byte8_09 "SBMU硬件版本号Byte8对应的ASCII码";
CM_ SG_ 2416242250 S2P_Cfg3_HW_Ver_Byte1_10 "SBMU硬件版本号最低字节Byte1对应的ASCII码";
CM_ SG_ 2416242250 S2P_Cfg3_HW_Ver_Byte2_10 "SBMU硬件版本号Byte2对应的ASCII码";
CM_ SG_ 2416242250 S2P_Cfg3_HW_Ver_Byte3_10 "SBMU硬件版本号Byte3对应的ASCII码";
CM_ SG_ 2416242250 S2P_Cfg3_HW_Ver_Byte4_10 "SBMU硬件版本号Byte4对应的ASCII码";
CM_ SG_ 2416242250 S2P_Cfg3_HW_Ver_Byte5_10 "SBMU硬件版本号Byte5对应的ASCII码";
CM_ SG_ 2416242250 S2P_Cfg3_HW_Ver_Byte6_10 "SBMU硬件版本号Byte6对应的ASCII码";
CM_ SG_ 2416242250 S2P_Cfg3_HW_Ver_Byte7_10 "SBMU硬件版本号Byte7对应的ASCII码";
CM_ SG_ 2416242250 S2P_Cfg3_HW_Ver_Byte8_10 "SBMU硬件版本号Byte8对应的ASCII码";
CM_ SG_ 2416242251 S2P_Cfg3_HW_Ver_Byte1_11 "SBMU硬件版本号最低字节Byte1对应的ASCII码";
CM_ SG_ 2416242251 S2P_Cfg3_HW_Ver_Byte2_11 "SBMU硬件版本号Byte2对应的ASCII码";
CM_ SG_ 2416242251 S2P_Cfg3_HW_Ver_Byte3_11 "SBMU硬件版本号Byte3对应的ASCII码";
CM_ SG_ 2416242251 S2P_Cfg3_HW_Ver_Byte4_11 "SBMU硬件版本号Byte4对应的ASCII码";
CM_ SG_ 2416242251 S2P_Cfg3_HW_Ver_Byte5_11 "SBMU硬件版本号Byte5对应的ASCII码";
CM_ SG_ 2416242251 S2P_Cfg3_HW_Ver_Byte6_11 "SBMU硬件版本号Byte6对应的ASCII码";
CM_ SG_ 2416242251 S2P_Cfg3_HW_Ver_Byte7_11 "SBMU硬件版本号Byte7对应的ASCII码";
CM_ SG_ 2416242251 S2P_Cfg3_HW_Ver_Byte8_11 "SBMU硬件版本号Byte8对应的ASCII码";
CM_ SG_ 2416242252 S2P_Cfg3_HW_Ver_Byte1_12 "SBMU硬件版本号最低字节Byte1对应的ASCII码";
CM_ SG_ 2416242252 S2P_Cfg3_HW_Ver_Byte2_12 "SBMU硬件版本号Byte2对应的ASCII码";
CM_ SG_ 2416242252 S2P_Cfg3_HW_Ver_Byte3_12 "SBMU硬件版本号Byte3对应的ASCII码";
CM_ SG_ 2416242252 S2P_Cfg3_HW_Ver_Byte4_12 "SBMU硬件版本号Byte4对应的ASCII码";
CM_ SG_ 2416242252 S2P_Cfg3_HW_Ver_Byte5_12 "SBMU硬件版本号Byte5对应的ASCII码";
CM_ SG_ 2416242252 S2P_Cfg3_HW_Ver_Byte6_12 "SBMU硬件版本号Byte6对应的ASCII码";
CM_ SG_ 2416242252 S2P_Cfg3_HW_Ver_Byte7_12 "SBMU硬件版本号Byte7对应的ASCII码";
CM_ SG_ 2416242252 S2P_Cfg3_HW_Ver_Byte8_12 "SBMU硬件版本号Byte8对应的ASCII码";
CM_ SG_ 2416242253 S2P_Cfg3_HW_Ver_Byte1_13 "SBMU硬件版本号最低字节Byte1对应的ASCII码";
CM_ SG_ 2416242253 S2P_Cfg3_HW_Ver_Byte2_13 "SBMU硬件版本号Byte2对应的ASCII码";
CM_ SG_ 2416242253 S2P_Cfg3_HW_Ver_Byte3_13 "SBMU硬件版本号Byte3对应的ASCII码";
CM_ SG_ 2416242253 S2P_Cfg3_HW_Ver_Byte4_13 "SBMU硬件版本号Byte4对应的ASCII码";
CM_ SG_ 2416242253 S2P_Cfg3_HW_Ver_Byte5_13 "SBMU硬件版本号Byte5对应的ASCII码";
CM_ SG_ 2416242253 S2P_Cfg3_HW_Ver_Byte6_13 "SBMU硬件版本号Byte6对应的ASCII码";
CM_ SG_ 2416242253 S2P_Cfg3_HW_Ver_Byte7_13 "SBMU硬件版本号Byte7对应的ASCII码";
CM_ SG_ 2416242253 S2P_Cfg3_HW_Ver_Byte8_13 "SBMU硬件版本号Byte8对应的ASCII码";
CM_ SG_ 2416242254 S2P_Cfg3_HW_Ver_Byte1_14 "SBMU硬件版本号最低字节Byte1对应的ASCII码";
CM_ SG_ 2416242254 S2P_Cfg3_HW_Ver_Byte2_14 "SBMU硬件版本号Byte2对应的ASCII码";
CM_ SG_ 2416242254 S2P_Cfg3_HW_Ver_Byte3_14 "SBMU硬件版本号Byte3对应的ASCII码";
CM_ SG_ 2416242254 S2P_Cfg3_HW_Ver_Byte4_14 "SBMU硬件版本号Byte4对应的ASCII码";
CM_ SG_ 2416242254 S2P_Cfg3_HW_Ver_Byte5_14 "SBMU硬件版本号Byte5对应的ASCII码";
CM_ SG_ 2416242254 S2P_Cfg3_HW_Ver_Byte6_14 "SBMU硬件版本号Byte6对应的ASCII码";
CM_ SG_ 2416242254 S2P_Cfg3_HW_Ver_Byte7_14 "SBMU硬件版本号Byte7对应的ASCII码";
CM_ SG_ 2416242254 S2P_Cfg3_HW_Ver_Byte8_14 "SBMU硬件版本号Byte8对应的ASCII码";
CM_ SG_ 2416242255 S2P_Cfg3_HW_Ver_Byte1_15 "SBMU硬件版本号最低字节Byte1对应的ASCII码";
CM_ SG_ 2416242255 S2P_Cfg3_HW_Ver_Byte2_15 "SBMU硬件版本号Byte2对应的ASCII码";
CM_ SG_ 2416242255 S2P_Cfg3_HW_Ver_Byte3_15 "SBMU硬件版本号Byte3对应的ASCII码";
CM_ SG_ 2416242255 S2P_Cfg3_HW_Ver_Byte4_15 "SBMU硬件版本号Byte4对应的ASCII码";
CM_ SG_ 2416242255 S2P_Cfg3_HW_Ver_Byte5_15 "SBMU硬件版本号Byte5对应的ASCII码";
CM_ SG_ 2416242255 S2P_Cfg3_HW_Ver_Byte6_15 "SBMU硬件版本号Byte6对应的ASCII码";
CM_ SG_ 2416242255 S2P_Cfg3_HW_Ver_Byte7_15 "SBMU硬件版本号Byte7对应的ASCII码";
CM_ SG_ 2416242255 S2P_Cfg3_HW_Ver_Byte8_15 "SBMU硬件版本号Byte8对应的ASCII码";
CM_ SG_ 2416242256 S2P_Cfg3_HW_Ver_Byte1_16 "SBMU硬件版本号最低字节Byte1对应的ASCII码";
CM_ SG_ 2416242256 S2P_Cfg3_HW_Ver_Byte2_16 "SBMU硬件版本号Byte2对应的ASCII码";
CM_ SG_ 2416242256 S2P_Cfg3_HW_Ver_Byte3_16 "SBMU硬件版本号Byte3对应的ASCII码";
CM_ SG_ 2416242256 S2P_Cfg3_HW_Ver_Byte4_16 "SBMU硬件版本号Byte4对应的ASCII码";
CM_ SG_ 2416242256 S2P_Cfg3_HW_Ver_Byte5_16 "SBMU硬件版本号Byte5对应的ASCII码";
CM_ SG_ 2416242256 S2P_Cfg3_HW_Ver_Byte6_16 "SBMU硬件版本号Byte6对应的ASCII码";
CM_ SG_ 2416242256 S2P_Cfg3_HW_Ver_Byte7_16 "SBMU硬件版本号Byte7对应的ASCII码";
CM_ SG_ 2416242256 S2P_Cfg3_HW_Ver_Byte8_16 "SBMU硬件版本号Byte8对应的ASCII码";
CM_ SG_ 2416242257 S2P_Cfg3_HW_Ver_Byte1_17 "SBMU硬件版本号最低字节Byte1对应的ASCII码";
CM_ SG_ 2416242257 S2P_Cfg3_HW_Ver_Byte2_17 "SBMU硬件版本号Byte2对应的ASCII码";
CM_ SG_ 2416242257 S2P_Cfg3_HW_Ver_Byte3_17 "SBMU硬件版本号Byte3对应的ASCII码";
CM_ SG_ 2416242257 S2P_Cfg3_HW_Ver_Byte4_17 "SBMU硬件版本号Byte4对应的ASCII码";
CM_ SG_ 2416242257 S2P_Cfg3_HW_Ver_Byte5_17 "SBMU硬件版本号Byte5对应的ASCII码";
CM_ SG_ 2416242257 S2P_Cfg3_HW_Ver_Byte6_17 "SBMU硬件版本号Byte6对应的ASCII码";
CM_ SG_ 2416242257 S2P_Cfg3_HW_Ver_Byte7_17 "SBMU硬件版本号Byte7对应的ASCII码";
CM_ SG_ 2416242257 S2P_Cfg3_HW_Ver_Byte8_17 "SBMU硬件版本号Byte8对应的ASCII码";
CM_ SG_ 2416242258 S2P_Cfg3_HW_Ver_Byte1_18 "SBMU硬件版本号最低字节Byte1对应的ASCII码";
CM_ SG_ 2416242258 S2P_Cfg3_HW_Ver_Byte2_18 "SBMU硬件版本号Byte2对应的ASCII码";
CM_ SG_ 2416242258 S2P_Cfg3_HW_Ver_Byte3_18 "SBMU硬件版本号Byte3对应的ASCII码";
CM_ SG_ 2416242258 S2P_Cfg3_HW_Ver_Byte4_18 "SBMU硬件版本号Byte4对应的ASCII码";
CM_ SG_ 2416242258 S2P_Cfg3_HW_Ver_Byte5_18 "SBMU硬件版本号Byte5对应的ASCII码";
CM_ SG_ 2416242258 S2P_Cfg3_HW_Ver_Byte6_18 "SBMU硬件版本号Byte6对应的ASCII码";
CM_ SG_ 2416242258 S2P_Cfg3_HW_Ver_Byte7_18 "SBMU硬件版本号Byte7对应的ASCII码";
CM_ SG_ 2416242258 S2P_Cfg3_HW_Ver_Byte8_18 "SBMU硬件版本号Byte8对应的ASCII码";
CM_ SG_ 2416242259 S2P_Cfg3_HW_Ver_Byte1_19 "SBMU硬件版本号最低字节Byte1对应的ASCII码";
CM_ SG_ 2416242259 S2P_Cfg3_HW_Ver_Byte2_19 "SBMU硬件版本号Byte2对应的ASCII码";
CM_ SG_ 2416242259 S2P_Cfg3_HW_Ver_Byte3_19 "SBMU硬件版本号Byte3对应的ASCII码";
CM_ SG_ 2416242259 S2P_Cfg3_HW_Ver_Byte4_19 "SBMU硬件版本号Byte4对应的ASCII码";
CM_ SG_ 2416242259 S2P_Cfg3_HW_Ver_Byte5_19 "SBMU硬件版本号Byte5对应的ASCII码";
CM_ SG_ 2416242259 S2P_Cfg3_HW_Ver_Byte6_19 "SBMU硬件版本号Byte6对应的ASCII码";
CM_ SG_ 2416242259 S2P_Cfg3_HW_Ver_Byte7_19 "SBMU硬件版本号Byte7对应的ASCII码";
CM_ SG_ 2416242259 S2P_Cfg3_HW_Ver_Byte8_19 "SBMU硬件版本号Byte8对应的ASCII码";
CM_ SG_ 2416242260 S2P_Cfg3_HW_Ver_Byte1_20 "SBMU硬件版本号最低字节Byte1对应的ASCII码";
CM_ SG_ 2416242260 S2P_Cfg3_HW_Ver_Byte2_20 "SBMU硬件版本号Byte2对应的ASCII码";
CM_ SG_ 2416242260 S2P_Cfg3_HW_Ver_Byte3_20 "SBMU硬件版本号Byte3对应的ASCII码";
CM_ SG_ 2416242260 S2P_Cfg3_HW_Ver_Byte4_20 "SBMU硬件版本号Byte4对应的ASCII码";
CM_ SG_ 2416242260 S2P_Cfg3_HW_Ver_Byte5_20 "SBMU硬件版本号Byte5对应的ASCII码";
CM_ SG_ 2416242260 S2P_Cfg3_HW_Ver_Byte6_20 "SBMU硬件版本号Byte6对应的ASCII码";
CM_ SG_ 2416242260 S2P_Cfg3_HW_Ver_Byte7_20 "SBMU硬件版本号Byte7对应的ASCII码";
CM_ SG_ 2416242260 S2P_Cfg3_HW_Ver_Byte8_20 "SBMU硬件版本号Byte8对应的ASCII码";
CM_ SG_ 2416242261 S2P_Cfg3_HW_Ver_Byte1_21 "SBMU硬件版本号最低字节Byte1对应的ASCII码";
CM_ SG_ 2416242261 S2P_Cfg3_HW_Ver_Byte2_21 "SBMU硬件版本号Byte2对应的ASCII码";
CM_ SG_ 2416242261 S2P_Cfg3_HW_Ver_Byte3_21 "SBMU硬件版本号Byte3对应的ASCII码";
CM_ SG_ 2416242261 S2P_Cfg3_HW_Ver_Byte4_21 "SBMU硬件版本号Byte4对应的ASCII码";
CM_ SG_ 2416242261 S2P_Cfg3_HW_Ver_Byte5_21 "SBMU硬件版本号Byte5对应的ASCII码";
CM_ SG_ 2416242261 S2P_Cfg3_HW_Ver_Byte6_21 "SBMU硬件版本号Byte6对应的ASCII码";
CM_ SG_ 2416242261 S2P_Cfg3_HW_Ver_Byte7_21 "SBMU硬件版本号Byte7对应的ASCII码";
CM_ SG_ 2416242261 S2P_Cfg3_HW_Ver_Byte8_21 "SBMU硬件版本号Byte8对应的ASCII码";
CM_ SG_ 2416242262 S2P_Cfg3_HW_Ver_Byte1_22 "SBMU硬件版本号最低字节Byte1对应的ASCII码";
CM_ SG_ 2416242262 S2P_Cfg3_HW_Ver_Byte2_22 "SBMU硬件版本号Byte2对应的ASCII码";
CM_ SG_ 2416242262 S2P_Cfg3_HW_Ver_Byte3_22 "SBMU硬件版本号Byte3对应的ASCII码";
CM_ SG_ 2416242262 S2P_Cfg3_HW_Ver_Byte4_22 "SBMU硬件版本号Byte4对应的ASCII码";
CM_ SG_ 2416242262 S2P_Cfg3_HW_Ver_Byte5_22 "SBMU硬件版本号Byte5对应的ASCII码";
CM_ SG_ 2416242262 S2P_Cfg3_HW_Ver_Byte6_22 "SBMU硬件版本号Byte6对应的ASCII码";
CM_ SG_ 2416242262 S2P_Cfg3_HW_Ver_Byte7_22 "SBMU硬件版本号Byte7对应的ASCII码";
CM_ SG_ 2416242262 S2P_Cfg3_HW_Ver_Byte8_22 "SBMU硬件版本号Byte8对应的ASCII码";
CM_ SG_ 2416242263 S2P_Cfg3_HW_Ver_Byte1_23 "SBMU硬件版本号最低字节Byte1对应的ASCII码";
CM_ SG_ 2416242263 S2P_Cfg3_HW_Ver_Byte2_23 "SBMU硬件版本号Byte2对应的ASCII码";
CM_ SG_ 2416242263 S2P_Cfg3_HW_Ver_Byte3_23 "SBMU硬件版本号Byte3对应的ASCII码";
CM_ SG_ 2416242263 S2P_Cfg3_HW_Ver_Byte4_23 "SBMU硬件版本号Byte4对应的ASCII码";
CM_ SG_ 2416242263 S2P_Cfg3_HW_Ver_Byte5_23 "SBMU硬件版本号Byte5对应的ASCII码";
CM_ SG_ 2416242263 S2P_Cfg3_HW_Ver_Byte6_23 "SBMU硬件版本号Byte6对应的ASCII码";
CM_ SG_ 2416242263 S2P_Cfg3_HW_Ver_Byte7_23 "SBMU硬件版本号Byte7对应的ASCII码";
CM_ SG_ 2416242263 S2P_Cfg3_HW_Ver_Byte8_23 "SBMU硬件版本号Byte8对应的ASCII码";
CM_ SG_ 2416242264 S2P_Cfg3_HW_Ver_Byte1_24 "SBMU硬件版本号最低字节Byte1对应的ASCII码";
CM_ SG_ 2416242264 S2P_Cfg3_HW_Ver_Byte2_24 "SBMU硬件版本号Byte2对应的ASCII码";
CM_ SG_ 2416242264 S2P_Cfg3_HW_Ver_Byte3_24 "SBMU硬件版本号Byte3对应的ASCII码";
CM_ SG_ 2416242264 S2P_Cfg3_HW_Ver_Byte4_24 "SBMU硬件版本号Byte4对应的ASCII码";
CM_ SG_ 2416242264 S2P_Cfg3_HW_Ver_Byte5_24 "SBMU硬件版本号Byte5对应的ASCII码";
CM_ SG_ 2416242264 S2P_Cfg3_HW_Ver_Byte6_24 "SBMU硬件版本号Byte6对应的ASCII码";
CM_ SG_ 2416242264 S2P_Cfg3_HW_Ver_Byte7_24 "SBMU硬件版本号Byte7对应的ASCII码";
CM_ SG_ 2416242264 S2P_Cfg3_HW_Ver_Byte8_24 "SBMU硬件版本号Byte8对应的ASCII码";
CM_ SG_ 2416242265 S2P_Cfg3_HW_Ver_Byte1_25 "SBMU硬件版本号最低字节Byte1对应的ASCII码";
CM_ SG_ 2416242265 S2P_Cfg3_HW_Ver_Byte2_25 "SBMU硬件版本号Byte2对应的ASCII码";
CM_ SG_ 2416242265 S2P_Cfg3_HW_Ver_Byte3_25 "SBMU硬件版本号Byte3对应的ASCII码";
CM_ SG_ 2416242265 S2P_Cfg3_HW_Ver_Byte4_25 "SBMU硬件版本号Byte4对应的ASCII码";
CM_ SG_ 2416242265 S2P_Cfg3_HW_Ver_Byte5_25 "SBMU硬件版本号Byte5对应的ASCII码";
CM_ SG_ 2416242265 S2P_Cfg3_HW_Ver_Byte6_25 "SBMU硬件版本号Byte6对应的ASCII码";
CM_ SG_ 2416242265 S2P_Cfg3_HW_Ver_Byte7_25 "SBMU硬件版本号Byte7对应的ASCII码";
CM_ SG_ 2416242265 S2P_Cfg3_HW_Ver_Byte8_25 "SBMU硬件版本号Byte8对应的ASCII码";
CM_ SG_ 2416242266 S2P_Cfg3_HW_Ver_Byte1_26 "SBMU硬件版本号最低字节Byte1对应的ASCII码";
CM_ SG_ 2416242266 S2P_Cfg3_HW_Ver_Byte2_26 "SBMU硬件版本号Byte2对应的ASCII码";
CM_ SG_ 2416242266 S2P_Cfg3_HW_Ver_Byte3_26 "SBMU硬件版本号Byte3对应的ASCII码";
CM_ SG_ 2416242266 S2P_Cfg3_HW_Ver_Byte4_26 "SBMU硬件版本号Byte4对应的ASCII码";
CM_ SG_ 2416242266 S2P_Cfg3_HW_Ver_Byte5_26 "SBMU硬件版本号Byte5对应的ASCII码";
CM_ SG_ 2416242266 S2P_Cfg3_HW_Ver_Byte6_26 "SBMU硬件版本号Byte6对应的ASCII码";
CM_ SG_ 2416242266 S2P_Cfg3_HW_Ver_Byte7_26 "SBMU硬件版本号Byte7对应的ASCII码";
CM_ SG_ 2416242266 S2P_Cfg3_HW_Ver_Byte8_26 "SBMU硬件版本号Byte8对应的ASCII码";
CM_ SG_ 2416242267 S2P_Cfg3_HW_Ver_Byte1_27 "SBMU硬件版本号最低字节Byte1对应的ASCII码";
CM_ SG_ 2416242267 S2P_Cfg3_HW_Ver_Byte2_27 "SBMU硬件版本号Byte2对应的ASCII码";
CM_ SG_ 2416242267 S2P_Cfg3_HW_Ver_Byte3_27 "SBMU硬件版本号Byte3对应的ASCII码";
CM_ SG_ 2416242267 S2P_Cfg3_HW_Ver_Byte4_27 "SBMU硬件版本号Byte4对应的ASCII码";
CM_ SG_ 2416242267 S2P_Cfg3_HW_Ver_Byte5_27 "SBMU硬件版本号Byte5对应的ASCII码";
CM_ SG_ 2416242267 S2P_Cfg3_HW_Ver_Byte6_27 "SBMU硬件版本号Byte6对应的ASCII码";
CM_ SG_ 2416242267 S2P_Cfg3_HW_Ver_Byte7_27 "SBMU硬件版本号Byte7对应的ASCII码";
CM_ SG_ 2416242267 S2P_Cfg3_HW_Ver_Byte8_27 "SBMU硬件版本号Byte8对应的ASCII码";
CM_ SG_ 2416242268 S2P_Cfg3_HW_Ver_Byte1_28 "SBMU硬件版本号最低字节Byte1对应的ASCII码";
CM_ SG_ 2416242268 S2P_Cfg3_HW_Ver_Byte2_28 "SBMU硬件版本号Byte2对应的ASCII码";
CM_ SG_ 2416242268 S2P_Cfg3_HW_Ver_Byte3_28 "SBMU硬件版本号Byte3对应的ASCII码";
CM_ SG_ 2416242268 S2P_Cfg3_HW_Ver_Byte4_28 "SBMU硬件版本号Byte4对应的ASCII码";
CM_ SG_ 2416242268 S2P_Cfg3_HW_Ver_Byte5_28 "SBMU硬件版本号Byte5对应的ASCII码";
CM_ SG_ 2416242268 S2P_Cfg3_HW_Ver_Byte6_28 "SBMU硬件版本号Byte6对应的ASCII码";
CM_ SG_ 2416242268 S2P_Cfg3_HW_Ver_Byte7_28 "SBMU硬件版本号Byte7对应的ASCII码";
CM_ SG_ 2416242268 S2P_Cfg3_HW_Ver_Byte8_28 "SBMU硬件版本号Byte8对应的ASCII码";
CM_ SG_ 2416242269 S2P_Cfg3_HW_Ver_Byte1_29 "SBMU硬件版本号最低字节Byte1对应的ASCII码";
CM_ SG_ 2416242269 S2P_Cfg3_HW_Ver_Byte2_29 "SBMU硬件版本号Byte2对应的ASCII码";
CM_ SG_ 2416242269 S2P_Cfg3_HW_Ver_Byte3_29 "SBMU硬件版本号Byte3对应的ASCII码";
CM_ SG_ 2416242269 S2P_Cfg3_HW_Ver_Byte4_29 "SBMU硬件版本号Byte4对应的ASCII码";
CM_ SG_ 2416242269 S2P_Cfg3_HW_Ver_Byte5_29 "SBMU硬件版本号Byte5对应的ASCII码";
CM_ SG_ 2416242269 S2P_Cfg3_HW_Ver_Byte6_29 "SBMU硬件版本号Byte6对应的ASCII码";
CM_ SG_ 2416242269 S2P_Cfg3_HW_Ver_Byte7_29 "SBMU硬件版本号Byte7对应的ASCII码";
CM_ SG_ 2416242269 S2P_Cfg3_HW_Ver_Byte8_29 "SBMU硬件版本号Byte8对应的ASCII码";
CM_ SG_ 2416242270 S2P_Cfg3_HW_Ver_Byte1_30 "SBMU硬件版本号最低字节Byte1对应的ASCII码";
CM_ SG_ 2416242270 S2P_Cfg3_HW_Ver_Byte2_30 "SBMU硬件版本号Byte2对应的ASCII码";
CM_ SG_ 2416242270 S2P_Cfg3_HW_Ver_Byte3_30 "SBMU硬件版本号Byte3对应的ASCII码";
CM_ SG_ 2416242270 S2P_Cfg3_HW_Ver_Byte4_30 "SBMU硬件版本号Byte4对应的ASCII码";
CM_ SG_ 2416242270 S2P_Cfg3_HW_Ver_Byte5_30 "SBMU硬件版本号Byte5对应的ASCII码";
CM_ SG_ 2416242270 S2P_Cfg3_HW_Ver_Byte6_30 "SBMU硬件版本号Byte6对应的ASCII码";
CM_ SG_ 2416242270 S2P_Cfg3_HW_Ver_Byte7_30 "SBMU硬件版本号Byte7对应的ASCII码";
CM_ SG_ 2416242270 S2P_Cfg3_HW_Ver_Byte8_30 "SBMU硬件版本号Byte8对应的ASCII码";
CM_ SG_ 2416242271 S2P_Cfg3_HW_Ver_Byte1_31 "SBMU硬件版本号最低字节Byte1对应的ASCII码";
CM_ SG_ 2416242271 S2P_Cfg3_HW_Ver_Byte2_31 "SBMU硬件版本号Byte2对应的ASCII码";
CM_ SG_ 2416242271 S2P_Cfg3_HW_Ver_Byte3_31 "SBMU硬件版本号Byte3对应的ASCII码";
CM_ SG_ 2416242271 S2P_Cfg3_HW_Ver_Byte4_31 "SBMU硬件版本号Byte4对应的ASCII码";
CM_ SG_ 2416242271 S2P_Cfg3_HW_Ver_Byte5_31 "SBMU硬件版本号Byte5对应的ASCII码";
CM_ SG_ 2416242271 S2P_Cfg3_HW_Ver_Byte6_31 "SBMU硬件版本号Byte6对应的ASCII码";
CM_ SG_ 2416242271 S2P_Cfg3_HW_Ver_Byte7_31 "SBMU硬件版本号Byte7对应的ASCII码";
CM_ SG_ 2416242271 S2P_Cfg3_HW_Ver_Byte8_31 "SBMU硬件版本号Byte8对应的ASCII码";
CM_ SG_ 2416242272 S2P_Cfg3_HW_Ver_Byte1_32 "SBMU硬件版本号最低字节Byte1对应的ASCII码";
CM_ SG_ 2416242272 S2P_Cfg3_HW_Ver_Byte2_32 "SBMU硬件版本号Byte2对应的ASCII码";
CM_ SG_ 2416242272 S2P_Cfg3_HW_Ver_Byte3_32 "SBMU硬件版本号Byte3对应的ASCII码";
CM_ SG_ 2416242272 S2P_Cfg3_HW_Ver_Byte4_32 "SBMU硬件版本号Byte4对应的ASCII码";
CM_ SG_ 2416242272 S2P_Cfg3_HW_Ver_Byte5_32 "SBMU硬件版本号Byte5对应的ASCII码";
CM_ SG_ 2416242272 S2P_Cfg3_HW_Ver_Byte6_32 "SBMU硬件版本号Byte6对应的ASCII码";
CM_ SG_ 2416242272 S2P_Cfg3_HW_Ver_Byte7_32 "SBMU硬件版本号Byte7对应的ASCII码";
CM_ SG_ 2416242272 S2P_Cfg3_HW_Ver_Byte8_32 "SBMU硬件版本号Byte8对应的ASCII码";
CM_ SG_ 2416242273 S2P_Cfg3_HW_Ver_Byte1_33 "SBMU硬件版本号最低字节Byte1对应的ASCII码";
CM_ SG_ 2416242273 S2P_Cfg3_HW_Ver_Byte2_33 "SBMU硬件版本号Byte2对应的ASCII码";
CM_ SG_ 2416242273 S2P_Cfg3_HW_Ver_Byte3_33 "SBMU硬件版本号Byte3对应的ASCII码";
CM_ SG_ 2416242273 S2P_Cfg3_HW_Ver_Byte4_33 "SBMU硬件版本号Byte4对应的ASCII码";
CM_ SG_ 2416242273 S2P_Cfg3_HW_Ver_Byte5_33 "SBMU硬件版本号Byte5对应的ASCII码";
CM_ SG_ 2416242273 S2P_Cfg3_HW_Ver_Byte6_33 "SBMU硬件版本号Byte6对应的ASCII码";
CM_ SG_ 2416242273 S2P_Cfg3_HW_Ver_Byte7_33 "SBMU硬件版本号Byte7对应的ASCII码";
CM_ SG_ 2416242273 S2P_Cfg3_HW_Ver_Byte8_33 "SBMU硬件版本号Byte8对应的ASCII码";
CM_ SG_ 2416242274 S2P_Cfg3_HW_Ver_Byte1_34 "SBMU硬件版本号最低字节Byte1对应的ASCII码";
CM_ SG_ 2416242274 S2P_Cfg3_HW_Ver_Byte2_34 "SBMU硬件版本号Byte2对应的ASCII码";
CM_ SG_ 2416242274 S2P_Cfg3_HW_Ver_Byte3_34 "SBMU硬件版本号Byte3对应的ASCII码";
CM_ SG_ 2416242274 S2P_Cfg3_HW_Ver_Byte4_34 "SBMU硬件版本号Byte4对应的ASCII码";
CM_ SG_ 2416242274 S2P_Cfg3_HW_Ver_Byte5_34 "SBMU硬件版本号Byte5对应的ASCII码";
CM_ SG_ 2416242274 S2P_Cfg3_HW_Ver_Byte6_34 "SBMU硬件版本号Byte6对应的ASCII码";
CM_ SG_ 2416242274 S2P_Cfg3_HW_Ver_Byte7_34 "SBMU硬件版本号Byte7对应的ASCII码";
CM_ SG_ 2416242274 S2P_Cfg3_HW_Ver_Byte8_34 "SBMU硬件版本号Byte8对应的ASCII码";
CM_ SG_ 2416242275 S2P_Cfg3_HW_Ver_Byte1_35 "SBMU硬件版本号最低字节Byte1对应的ASCII码";
CM_ SG_ 2416242275 S2P_Cfg3_HW_Ver_Byte2_35 "SBMU硬件版本号Byte2对应的ASCII码";
CM_ SG_ 2416242275 S2P_Cfg3_HW_Ver_Byte3_35 "SBMU硬件版本号Byte3对应的ASCII码";
CM_ SG_ 2416242275 S2P_Cfg3_HW_Ver_Byte4_35 "SBMU硬件版本号Byte4对应的ASCII码";
CM_ SG_ 2416242275 S2P_Cfg3_HW_Ver_Byte5_35 "SBMU硬件版本号Byte5对应的ASCII码";
CM_ SG_ 2416242275 S2P_Cfg3_HW_Ver_Byte6_35 "SBMU硬件版本号Byte6对应的ASCII码";
CM_ SG_ 2416242275 S2P_Cfg3_HW_Ver_Byte7_35 "SBMU硬件版本号Byte7对应的ASCII码";
CM_ SG_ 2416242275 S2P_Cfg3_HW_Ver_Byte8_35 "SBMU硬件版本号Byte8对应的ASCII码";
CM_ SG_ 2416242276 S2P_Cfg3_HW_Ver_Byte1_36 "SBMU硬件版本号最低字节Byte1对应的ASCII码";
CM_ SG_ 2416242276 S2P_Cfg3_HW_Ver_Byte2_36 "SBMU硬件版本号Byte2对应的ASCII码";
CM_ SG_ 2416242276 S2P_Cfg3_HW_Ver_Byte3_36 "SBMU硬件版本号Byte3对应的ASCII码";
CM_ SG_ 2416242276 S2P_Cfg3_HW_Ver_Byte4_36 "SBMU硬件版本号Byte4对应的ASCII码";
CM_ SG_ 2416242276 S2P_Cfg3_HW_Ver_Byte5_36 "SBMU硬件版本号Byte5对应的ASCII码";
CM_ SG_ 2416242276 S2P_Cfg3_HW_Ver_Byte6_36 "SBMU硬件版本号Byte6对应的ASCII码";
CM_ SG_ 2416242276 S2P_Cfg3_HW_Ver_Byte7_36 "SBMU硬件版本号Byte7对应的ASCII码";
CM_ SG_ 2416242276 S2P_Cfg3_HW_Ver_Byte8_36 "SBMU硬件版本号Byte8对应的ASCII码";
CM_ SG_ 2416242277 S2P_Cfg3_HW_Ver_Byte1_37 "SBMU硬件版本号最低字节Byte1对应的ASCII码";
CM_ SG_ 2416242277 S2P_Cfg3_HW_Ver_Byte2_37 "SBMU硬件版本号Byte2对应的ASCII码";
CM_ SG_ 2416242277 S2P_Cfg3_HW_Ver_Byte3_37 "SBMU硬件版本号Byte3对应的ASCII码";
CM_ SG_ 2416242277 S2P_Cfg3_HW_Ver_Byte4_37 "SBMU硬件版本号Byte4对应的ASCII码";
CM_ SG_ 2416242277 S2P_Cfg3_HW_Ver_Byte5_37 "SBMU硬件版本号Byte5对应的ASCII码";
CM_ SG_ 2416242277 S2P_Cfg3_HW_Ver_Byte6_37 "SBMU硬件版本号Byte6对应的ASCII码";
CM_ SG_ 2416242277 S2P_Cfg3_HW_Ver_Byte7_37 "SBMU硬件版本号Byte7对应的ASCII码";
CM_ SG_ 2416242277 S2P_Cfg3_HW_Ver_Byte8_37 "SBMU硬件版本号Byte8对应的ASCII码";
CM_ SG_ 2416242278 S2P_Cfg3_HW_Ver_Byte1_38 "SBMU硬件版本号最低字节Byte1对应的ASCII码";
CM_ SG_ 2416242278 S2P_Cfg3_HW_Ver_Byte2_38 "SBMU硬件版本号Byte2对应的ASCII码";
CM_ SG_ 2416242278 S2P_Cfg3_HW_Ver_Byte3_38 "SBMU硬件版本号Byte3对应的ASCII码";
CM_ SG_ 2416242278 S2P_Cfg3_HW_Ver_Byte4_38 "SBMU硬件版本号Byte4对应的ASCII码";
CM_ SG_ 2416242278 S2P_Cfg3_HW_Ver_Byte5_38 "SBMU硬件版本号Byte5对应的ASCII码";
CM_ SG_ 2416242278 S2P_Cfg3_HW_Ver_Byte6_38 "SBMU硬件版本号Byte6对应的ASCII码";
CM_ SG_ 2416242278 S2P_Cfg3_HW_Ver_Byte7_38 "SBMU硬件版本号Byte7对应的ASCII码";
CM_ SG_ 2416242278 S2P_Cfg3_HW_Ver_Byte8_38 "SBMU硬件版本号Byte8对应的ASCII码";
CM_ SG_ 2416242279 S2P_Cfg3_HW_Ver_Byte1_39 "SBMU硬件版本号最低字节Byte1对应的ASCII码";
CM_ SG_ 2416242279 S2P_Cfg3_HW_Ver_Byte2_39 "SBMU硬件版本号Byte2对应的ASCII码";
CM_ SG_ 2416242279 S2P_Cfg3_HW_Ver_Byte3_39 "SBMU硬件版本号Byte3对应的ASCII码";
CM_ SG_ 2416242279 S2P_Cfg3_HW_Ver_Byte4_39 "SBMU硬件版本号Byte4对应的ASCII码";
CM_ SG_ 2416242279 S2P_Cfg3_HW_Ver_Byte5_39 "SBMU硬件版本号Byte5对应的ASCII码";
CM_ SG_ 2416242279 S2P_Cfg3_HW_Ver_Byte6_39 "SBMU硬件版本号Byte6对应的ASCII码";
CM_ SG_ 2416242279 S2P_Cfg3_HW_Ver_Byte7_39 "SBMU硬件版本号Byte7对应的ASCII码";
CM_ SG_ 2416242279 S2P_Cfg3_HW_Ver_Byte8_39 "SBMU硬件版本号Byte8对应的ASCII码";
CM_ SG_ 2416242280 S2P_Cfg3_HW_Ver_Byte1_40 "SBMU硬件版本号最低字节Byte1对应的ASCII码";
CM_ SG_ 2416242280 S2P_Cfg3_HW_Ver_Byte2_40 "SBMU硬件版本号Byte2对应的ASCII码";
CM_ SG_ 2416242280 S2P_Cfg3_HW_Ver_Byte3_40 "SBMU硬件版本号Byte3对应的ASCII码";
CM_ SG_ 2416242280 S2P_Cfg3_HW_Ver_Byte4_40 "SBMU硬件版本号Byte4对应的ASCII码";
CM_ SG_ 2416242280 S2P_Cfg3_HW_Ver_Byte5_40 "SBMU硬件版本号Byte5对应的ASCII码";
CM_ SG_ 2416242280 S2P_Cfg3_HW_Ver_Byte6_40 "SBMU硬件版本号Byte6对应的ASCII码";
CM_ SG_ 2416242280 S2P_Cfg3_HW_Ver_Byte7_40 "SBMU硬件版本号Byte7对应的ASCII码";
CM_ SG_ 2416242280 S2P_Cfg3_HW_Ver_Byte8_40 "SBMU硬件版本号Byte8对应的ASCII码";
CM_ SG_ 2416242281 S2P_Cfg3_HW_Ver_Byte1_41 "SBMU硬件版本号最低字节Byte1对应的ASCII码";
CM_ SG_ 2416242281 S2P_Cfg3_HW_Ver_Byte2_41 "SBMU硬件版本号Byte2对应的ASCII码";
CM_ SG_ 2416242281 S2P_Cfg3_HW_Ver_Byte3_41 "SBMU硬件版本号Byte3对应的ASCII码";
CM_ SG_ 2416242281 S2P_Cfg3_HW_Ver_Byte4_41 "SBMU硬件版本号Byte4对应的ASCII码";
CM_ SG_ 2416242281 S2P_Cfg3_HW_Ver_Byte5_41 "SBMU硬件版本号Byte5对应的ASCII码";
CM_ SG_ 2416242281 S2P_Cfg3_HW_Ver_Byte6_41 "SBMU硬件版本号Byte6对应的ASCII码";
CM_ SG_ 2416242281 S2P_Cfg3_HW_Ver_Byte7_41 "SBMU硬件版本号Byte7对应的ASCII码";
CM_ SG_ 2416242281 S2P_Cfg3_HW_Ver_Byte8_41 "SBMU硬件版本号Byte8对应的ASCII码";
CM_ SG_ 2416242282 S2P_Cfg3_HW_Ver_Byte1_42 "SBMU硬件版本号最低字节Byte1对应的ASCII码";
CM_ SG_ 2416242282 S2P_Cfg3_HW_Ver_Byte2_42 "SBMU硬件版本号Byte2对应的ASCII码";
CM_ SG_ 2416242282 S2P_Cfg3_HW_Ver_Byte3_42 "SBMU硬件版本号Byte3对应的ASCII码";
CM_ SG_ 2416242282 S2P_Cfg3_HW_Ver_Byte4_42 "SBMU硬件版本号Byte4对应的ASCII码";
CM_ SG_ 2416242282 S2P_Cfg3_HW_Ver_Byte5_42 "SBMU硬件版本号Byte5对应的ASCII码";
CM_ SG_ 2416242282 S2P_Cfg3_HW_Ver_Byte6_42 "SBMU硬件版本号Byte6对应的ASCII码";
CM_ SG_ 2416242282 S2P_Cfg3_HW_Ver_Byte7_42 "SBMU硬件版本号Byte7对应的ASCII码";
CM_ SG_ 2416242282 S2P_Cfg3_HW_Ver_Byte8_42 "SBMU硬件版本号Byte8对应的ASCII码";
CM_ SG_ 2416242283 S2P_Cfg3_HW_Ver_Byte1_43 "SBMU硬件版本号最低字节Byte1对应的ASCII码";
CM_ SG_ 2416242283 S2P_Cfg3_HW_Ver_Byte2_43 "SBMU硬件版本号Byte2对应的ASCII码";
CM_ SG_ 2416242283 S2P_Cfg3_HW_Ver_Byte3_43 "SBMU硬件版本号Byte3对应的ASCII码";
CM_ SG_ 2416242283 S2P_Cfg3_HW_Ver_Byte4_43 "SBMU硬件版本号Byte4对应的ASCII码";
CM_ SG_ 2416242283 S2P_Cfg3_HW_Ver_Byte5_43 "SBMU硬件版本号Byte5对应的ASCII码";
CM_ SG_ 2416242283 S2P_Cfg3_HW_Ver_Byte6_43 "SBMU硬件版本号Byte6对应的ASCII码";
CM_ SG_ 2416242283 S2P_Cfg3_HW_Ver_Byte7_43 "SBMU硬件版本号Byte7对应的ASCII码";
CM_ SG_ 2416242283 S2P_Cfg3_HW_Ver_Byte8_43 "SBMU硬件版本号Byte8对应的ASCII码";
CM_ SG_ 2416242284 S2P_Cfg3_HW_Ver_Byte1_44 "SBMU硬件版本号最低字节Byte1对应的ASCII码";
CM_ SG_ 2416242284 S2P_Cfg3_HW_Ver_Byte2_44 "SBMU硬件版本号Byte2对应的ASCII码";
CM_ SG_ 2416242284 S2P_Cfg3_HW_Ver_Byte3_44 "SBMU硬件版本号Byte3对应的ASCII码";
CM_ SG_ 2416242284 S2P_Cfg3_HW_Ver_Byte4_44 "SBMU硬件版本号Byte4对应的ASCII码";
CM_ SG_ 2416242284 S2P_Cfg3_HW_Ver_Byte5_44 "SBMU硬件版本号Byte5对应的ASCII码";
CM_ SG_ 2416242284 S2P_Cfg3_HW_Ver_Byte6_44 "SBMU硬件版本号Byte6对应的ASCII码";
CM_ SG_ 2416242284 S2P_Cfg3_HW_Ver_Byte7_44 "SBMU硬件版本号Byte7对应的ASCII码";
CM_ SG_ 2416242284 S2P_Cfg3_HW_Ver_Byte8_44 "SBMU硬件版本号Byte8对应的ASCII码";
CM_ SG_ 2416242285 S2P_Cfg3_HW_Ver_Byte1_45 "SBMU硬件版本号最低字节Byte1对应的ASCII码";
CM_ SG_ 2416242285 S2P_Cfg3_HW_Ver_Byte2_45 "SBMU硬件版本号Byte2对应的ASCII码";
CM_ SG_ 2416242285 S2P_Cfg3_HW_Ver_Byte3_45 "SBMU硬件版本号Byte3对应的ASCII码";
CM_ SG_ 2416242285 S2P_Cfg3_HW_Ver_Byte4_45 "SBMU硬件版本号Byte4对应的ASCII码";
CM_ SG_ 2416242285 S2P_Cfg3_HW_Ver_Byte5_45 "SBMU硬件版本号Byte5对应的ASCII码";
CM_ SG_ 2416242285 S2P_Cfg3_HW_Ver_Byte6_45 "SBMU硬件版本号Byte6对应的ASCII码";
CM_ SG_ 2416242285 S2P_Cfg3_HW_Ver_Byte7_45 "SBMU硬件版本号Byte7对应的ASCII码";
CM_ SG_ 2416242285 S2P_Cfg3_HW_Ver_Byte8_45 "SBMU硬件版本号Byte8对应的ASCII码";
CM_ SG_ 2416242286 S2P_Cfg3_HW_Ver_Byte1_46 "SBMU硬件版本号最低字节Byte1对应的ASCII码";
CM_ SG_ 2416242286 S2P_Cfg3_HW_Ver_Byte2_46 "SBMU硬件版本号Byte2对应的ASCII码";
CM_ SG_ 2416242286 S2P_Cfg3_HW_Ver_Byte3_46 "SBMU硬件版本号Byte3对应的ASCII码";
CM_ SG_ 2416242286 S2P_Cfg3_HW_Ver_Byte4_46 "SBMU硬件版本号Byte4对应的ASCII码";
CM_ SG_ 2416242286 S2P_Cfg3_HW_Ver_Byte5_46 "SBMU硬件版本号Byte5对应的ASCII码";
CM_ SG_ 2416242286 S2P_Cfg3_HW_Ver_Byte6_46 "SBMU硬件版本号Byte6对应的ASCII码";
CM_ SG_ 2416242286 S2P_Cfg3_HW_Ver_Byte7_46 "SBMU硬件版本号Byte7对应的ASCII码";
CM_ SG_ 2416242286 S2P_Cfg3_HW_Ver_Byte8_46 "SBMU硬件版本号Byte8对应的ASCII码";
CM_ SG_ 2416242287 S2P_Cfg3_HW_Ver_Byte1_47 "SBMU硬件版本号最低字节Byte1对应的ASCII码";
CM_ SG_ 2416242287 S2P_Cfg3_HW_Ver_Byte2_47 "SBMU硬件版本号Byte2对应的ASCII码";
CM_ SG_ 2416242287 S2P_Cfg3_HW_Ver_Byte3_47 "SBMU硬件版本号Byte3对应的ASCII码";
CM_ SG_ 2416242287 S2P_Cfg3_HW_Ver_Byte4_47 "SBMU硬件版本号Byte4对应的ASCII码";
CM_ SG_ 2416242287 S2P_Cfg3_HW_Ver_Byte5_47 "SBMU硬件版本号Byte5对应的ASCII码";
CM_ SG_ 2416242287 S2P_Cfg3_HW_Ver_Byte6_47 "SBMU硬件版本号Byte6对应的ASCII码";
CM_ SG_ 2416242287 S2P_Cfg3_HW_Ver_Byte7_47 "SBMU硬件版本号Byte7对应的ASCII码";
CM_ SG_ 2416242287 S2P_Cfg3_HW_Ver_Byte8_47 "SBMU硬件版本号Byte8对应的ASCII码";
CM_ SG_ 2416242288 S2P_Cfg3_HW_Ver_Byte1_48 "SBMU硬件版本号最低字节Byte1对应的ASCII码";
CM_ SG_ 2416242288 S2P_Cfg3_HW_Ver_Byte2_48 "SBMU硬件版本号Byte2对应的ASCII码";
CM_ SG_ 2416242288 S2P_Cfg3_HW_Ver_Byte3_48 "SBMU硬件版本号Byte3对应的ASCII码";
CM_ SG_ 2416242288 S2P_Cfg3_HW_Ver_Byte4_48 "SBMU硬件版本号Byte4对应的ASCII码";
CM_ SG_ 2416242288 S2P_Cfg3_HW_Ver_Byte5_48 "SBMU硬件版本号Byte5对应的ASCII码";
CM_ SG_ 2416242288 S2P_Cfg3_HW_Ver_Byte6_48 "SBMU硬件版本号Byte6对应的ASCII码";
CM_ SG_ 2416242288 S2P_Cfg3_HW_Ver_Byte7_48 "SBMU硬件版本号Byte7对应的ASCII码";
CM_ SG_ 2416242288 S2P_Cfg3_HW_Ver_Byte8_48 "SBMU硬件版本号Byte8对应的ASCII码";
CM_ SG_ 2416242289 S2P_Cfg3_HW_Ver_Byte1_49 "SBMU硬件版本号最低字节Byte1对应的ASCII码";
CM_ SG_ 2416242289 S2P_Cfg3_HW_Ver_Byte2_49 "SBMU硬件版本号Byte2对应的ASCII码";
CM_ SG_ 2416242289 S2P_Cfg3_HW_Ver_Byte3_49 "SBMU硬件版本号Byte3对应的ASCII码";
CM_ SG_ 2416242289 S2P_Cfg3_HW_Ver_Byte4_49 "SBMU硬件版本号Byte4对应的ASCII码";
CM_ SG_ 2416242289 S2P_Cfg3_HW_Ver_Byte5_49 "SBMU硬件版本号Byte5对应的ASCII码";
CM_ SG_ 2416242289 S2P_Cfg3_HW_Ver_Byte6_49 "SBMU硬件版本号Byte6对应的ASCII码";
CM_ SG_ 2416242289 S2P_Cfg3_HW_Ver_Byte7_49 "SBMU硬件版本号Byte7对应的ASCII码";
CM_ SG_ 2416242289 S2P_Cfg3_HW_Ver_Byte8_49 "SBMU硬件版本号Byte8对应的ASCII码";
CM_ SG_ 2416242290 S2P_Cfg3_HW_Ver_Byte1_50 "SBMU硬件版本号最低字节Byte1对应的ASCII码";
CM_ SG_ 2416242290 S2P_Cfg3_HW_Ver_Byte2_50 "SBMU硬件版本号Byte2对应的ASCII码";
CM_ SG_ 2416242290 S2P_Cfg3_HW_Ver_Byte3_50 "SBMU硬件版本号Byte3对应的ASCII码";
CM_ SG_ 2416242290 S2P_Cfg3_HW_Ver_Byte4_50 "SBMU硬件版本号Byte4对应的ASCII码";
CM_ SG_ 2416242290 S2P_Cfg3_HW_Ver_Byte5_50 "SBMU硬件版本号Byte5对应的ASCII码";
CM_ SG_ 2416242290 S2P_Cfg3_HW_Ver_Byte6_50 "SBMU硬件版本号Byte6对应的ASCII码";
CM_ SG_ 2416242290 S2P_Cfg3_HW_Ver_Byte7_50 "SBMU硬件版本号Byte7对应的ASCII码";
CM_ SG_ 2416242290 S2P_Cfg3_HW_Ver_Byte8_50 "SBMU硬件版本号Byte8对应的ASCII码";
CM_ SG_ 2416242291 S2P_Cfg3_HW_Ver_Byte1_51 "SBMU硬件版本号最低字节Byte1对应的ASCII码";
CM_ SG_ 2416242291 S2P_Cfg3_HW_Ver_Byte2_51 "SBMU硬件版本号Byte2对应的ASCII码";
CM_ SG_ 2416242291 S2P_Cfg3_HW_Ver_Byte3_51 "SBMU硬件版本号Byte3对应的ASCII码";
CM_ SG_ 2416242291 S2P_Cfg3_HW_Ver_Byte4_51 "SBMU硬件版本号Byte4对应的ASCII码";
CM_ SG_ 2416242291 S2P_Cfg3_HW_Ver_Byte5_51 "SBMU硬件版本号Byte5对应的ASCII码";
CM_ SG_ 2416242291 S2P_Cfg3_HW_Ver_Byte6_51 "SBMU硬件版本号Byte6对应的ASCII码";
CM_ SG_ 2416242291 S2P_Cfg3_HW_Ver_Byte7_51 "SBMU硬件版本号Byte7对应的ASCII码";
CM_ SG_ 2416242291 S2P_Cfg3_HW_Ver_Byte8_51 "SBMU硬件版本号Byte8对应的ASCII码";
CM_ SG_ 2416242292 S2P_Cfg3_HW_Ver_Byte1_52 "SBMU硬件版本号最低字节Byte1对应的ASCII码";
CM_ SG_ 2416242292 S2P_Cfg3_HW_Ver_Byte2_52 "SBMU硬件版本号Byte2对应的ASCII码";
CM_ SG_ 2416242292 S2P_Cfg3_HW_Ver_Byte3_52 "SBMU硬件版本号Byte3对应的ASCII码";
CM_ SG_ 2416242292 S2P_Cfg3_HW_Ver_Byte4_52 "SBMU硬件版本号Byte4对应的ASCII码";
CM_ SG_ 2416242292 S2P_Cfg3_HW_Ver_Byte5_52 "SBMU硬件版本号Byte5对应的ASCII码";
CM_ SG_ 2416242292 S2P_Cfg3_HW_Ver_Byte6_52 "SBMU硬件版本号Byte6对应的ASCII码";
CM_ SG_ 2416242292 S2P_Cfg3_HW_Ver_Byte7_52 "SBMU硬件版本号Byte7对应的ASCII码";
CM_ SG_ 2416242292 S2P_Cfg3_HW_Ver_Byte8_52 "SBMU硬件版本号Byte8对应的ASCII码";
CM_ SG_ 2416242293 S2P_Cfg3_HW_Ver_Byte1_53 "SBMU硬件版本号最低字节Byte1对应的ASCII码";
CM_ SG_ 2416242293 S2P_Cfg3_HW_Ver_Byte2_53 "SBMU硬件版本号Byte2对应的ASCII码";
CM_ SG_ 2416242293 S2P_Cfg3_HW_Ver_Byte3_53 "SBMU硬件版本号Byte3对应的ASCII码";
CM_ SG_ 2416242293 S2P_Cfg3_HW_Ver_Byte4_53 "SBMU硬件版本号Byte4对应的ASCII码";
CM_ SG_ 2416242293 S2P_Cfg3_HW_Ver_Byte5_53 "SBMU硬件版本号Byte5对应的ASCII码";
CM_ SG_ 2416242293 S2P_Cfg3_HW_Ver_Byte6_53 "SBMU硬件版本号Byte6对应的ASCII码";
CM_ SG_ 2416242293 S2P_Cfg3_HW_Ver_Byte7_53 "SBMU硬件版本号Byte7对应的ASCII码";
CM_ SG_ 2416242293 S2P_Cfg3_HW_Ver_Byte8_53 "SBMU硬件版本号Byte8对应的ASCII码";
CM_ SG_ 2416242294 S2P_Cfg3_HW_Ver_Byte1_54 "SBMU硬件版本号最低字节Byte1对应的ASCII码";
CM_ SG_ 2416242294 S2P_Cfg3_HW_Ver_Byte2_54 "SBMU硬件版本号Byte2对应的ASCII码";
CM_ SG_ 2416242294 S2P_Cfg3_HW_Ver_Byte3_54 "SBMU硬件版本号Byte3对应的ASCII码";
CM_ SG_ 2416242294 S2P_Cfg3_HW_Ver_Byte4_54 "SBMU硬件版本号Byte4对应的ASCII码";
CM_ SG_ 2416242294 S2P_Cfg3_HW_Ver_Byte5_54 "SBMU硬件版本号Byte5对应的ASCII码";
CM_ SG_ 2416242294 S2P_Cfg3_HW_Ver_Byte6_54 "SBMU硬件版本号Byte6对应的ASCII码";
CM_ SG_ 2416242294 S2P_Cfg3_HW_Ver_Byte7_54 "SBMU硬件版本号Byte7对应的ASCII码";
CM_ SG_ 2416242294 S2P_Cfg3_HW_Ver_Byte8_54 "SBMU硬件版本号Byte8对应的ASCII码";
CM_ SG_ 2416242295 S2P_Cfg3_HW_Ver_Byte1_55 "SBMU硬件版本号最低字节Byte1对应的ASCII码";
CM_ SG_ 2416242295 S2P_Cfg3_HW_Ver_Byte2_55 "SBMU硬件版本号Byte2对应的ASCII码";
CM_ SG_ 2416242295 S2P_Cfg3_HW_Ver_Byte3_55 "SBMU硬件版本号Byte3对应的ASCII码";
CM_ SG_ 2416242295 S2P_Cfg3_HW_Ver_Byte4_55 "SBMU硬件版本号Byte4对应的ASCII码";
CM_ SG_ 2416242295 S2P_Cfg3_HW_Ver_Byte5_55 "SBMU硬件版本号Byte5对应的ASCII码";
CM_ SG_ 2416242295 S2P_Cfg3_HW_Ver_Byte6_55 "SBMU硬件版本号Byte6对应的ASCII码";
CM_ SG_ 2416242295 S2P_Cfg3_HW_Ver_Byte7_55 "SBMU硬件版本号Byte7对应的ASCII码";
CM_ SG_ 2416242295 S2P_Cfg3_HW_Ver_Byte8_55 "SBMU硬件版本号Byte8对应的ASCII码";
CM_ SG_ 2416242296 S2P_Cfg3_HW_Ver_Byte1_56 "SBMU硬件版本号最低字节Byte1对应的ASCII码";
CM_ SG_ 2416242296 S2P_Cfg3_HW_Ver_Byte2_56 "SBMU硬件版本号Byte2对应的ASCII码";
CM_ SG_ 2416242296 S2P_Cfg3_HW_Ver_Byte3_56 "SBMU硬件版本号Byte3对应的ASCII码";
CM_ SG_ 2416242296 S2P_Cfg3_HW_Ver_Byte4_56 "SBMU硬件版本号Byte4对应的ASCII码";
CM_ SG_ 2416242296 S2P_Cfg3_HW_Ver_Byte5_56 "SBMU硬件版本号Byte5对应的ASCII码";
CM_ SG_ 2416242296 S2P_Cfg3_HW_Ver_Byte6_56 "SBMU硬件版本号Byte6对应的ASCII码";
CM_ SG_ 2416242296 S2P_Cfg3_HW_Ver_Byte7_56 "SBMU硬件版本号Byte7对应的ASCII码";
CM_ SG_ 2416242296 S2P_Cfg3_HW_Ver_Byte8_56 "SBMU硬件版本号Byte8对应的ASCII码";
CM_ SG_ 2416242297 S2P_Cfg3_HW_Ver_Byte1_57 "SBMU硬件版本号最低字节Byte1对应的ASCII码";
CM_ SG_ 2416242297 S2P_Cfg3_HW_Ver_Byte2_57 "SBMU硬件版本号Byte2对应的ASCII码";
CM_ SG_ 2416242297 S2P_Cfg3_HW_Ver_Byte3_57 "SBMU硬件版本号Byte3对应的ASCII码";
CM_ SG_ 2416242297 S2P_Cfg3_HW_Ver_Byte4_57 "SBMU硬件版本号Byte4对应的ASCII码";
CM_ SG_ 2416242297 S2P_Cfg3_HW_Ver_Byte5_57 "SBMU硬件版本号Byte5对应的ASCII码";
CM_ SG_ 2416242297 S2P_Cfg3_HW_Ver_Byte6_57 "SBMU硬件版本号Byte6对应的ASCII码";
CM_ SG_ 2416242297 S2P_Cfg3_HW_Ver_Byte7_57 "SBMU硬件版本号Byte7对应的ASCII码";
CM_ SG_ 2416242297 S2P_Cfg3_HW_Ver_Byte8_57 "SBMU硬件版本号Byte8对应的ASCII码";
CM_ SG_ 2416242298 S2P_Cfg3_HW_Ver_Byte1_58 "SBMU硬件版本号最低字节Byte1对应的ASCII码";
CM_ SG_ 2416242298 S2P_Cfg3_HW_Ver_Byte2_58 "SBMU硬件版本号Byte2对应的ASCII码";
CM_ SG_ 2416242298 S2P_Cfg3_HW_Ver_Byte3_58 "SBMU硬件版本号Byte3对应的ASCII码";
CM_ SG_ 2416242298 S2P_Cfg3_HW_Ver_Byte4_58 "SBMU硬件版本号Byte4对应的ASCII码";
CM_ SG_ 2416242298 S2P_Cfg3_HW_Ver_Byte5_58 "SBMU硬件版本号Byte5对应的ASCII码";
CM_ SG_ 2416242298 S2P_Cfg3_HW_Ver_Byte6_58 "SBMU硬件版本号Byte6对应的ASCII码";
CM_ SG_ 2416242298 S2P_Cfg3_HW_Ver_Byte7_58 "SBMU硬件版本号Byte7对应的ASCII码";
CM_ SG_ 2416242298 S2P_Cfg3_HW_Ver_Byte8_58 "SBMU硬件版本号Byte8对应的ASCII码";
CM_ SG_ 2416242299 S2P_Cfg3_HW_Ver_Byte1_59 "SBMU硬件版本号最低字节Byte1对应的ASCII码";
CM_ SG_ 2416242299 S2P_Cfg3_HW_Ver_Byte2_59 "SBMU硬件版本号Byte2对应的ASCII码";
CM_ SG_ 2416242299 S2P_Cfg3_HW_Ver_Byte3_59 "SBMU硬件版本号Byte3对应的ASCII码";
CM_ SG_ 2416242299 S2P_Cfg3_HW_Ver_Byte4_59 "SBMU硬件版本号Byte4对应的ASCII码";
CM_ SG_ 2416242299 S2P_Cfg3_HW_Ver_Byte5_59 "SBMU硬件版本号Byte5对应的ASCII码";
CM_ SG_ 2416242299 S2P_Cfg3_HW_Ver_Byte6_59 "SBMU硬件版本号Byte6对应的ASCII码";
CM_ SG_ 2416242299 S2P_Cfg3_HW_Ver_Byte7_59 "SBMU硬件版本号Byte7对应的ASCII码";
CM_ SG_ 2416242299 S2P_Cfg3_HW_Ver_Byte8_59 "SBMU硬件版本号Byte8对应的ASCII码";
CM_ SG_ 2416242300 S2P_Cfg3_HW_Ver_Byte1_60 "SBMU硬件版本号最低字节Byte1对应的ASCII码";
CM_ SG_ 2416242300 S2P_Cfg3_HW_Ver_Byte2_60 "SBMU硬件版本号Byte2对应的ASCII码";
CM_ SG_ 2416242300 S2P_Cfg3_HW_Ver_Byte3_60 "SBMU硬件版本号Byte3对应的ASCII码";
CM_ SG_ 2416242300 S2P_Cfg3_HW_Ver_Byte4_60 "SBMU硬件版本号Byte4对应的ASCII码";
CM_ SG_ 2416242300 S2P_Cfg3_HW_Ver_Byte5_60 "SBMU硬件版本号Byte5对应的ASCII码";
CM_ SG_ 2416242300 S2P_Cfg3_HW_Ver_Byte6_60 "SBMU硬件版本号Byte6对应的ASCII码";
CM_ SG_ 2416242300 S2P_Cfg3_HW_Ver_Byte7_60 "SBMU硬件版本号Byte7对应的ASCII码";
CM_ SG_ 2416242300 S2P_Cfg3_HW_Ver_Byte8_60 "SBMU硬件版本号Byte8对应的ASCII码";
CM_ SG_ 2416242301 S2P_Cfg3_HW_Ver_Byte1_61 "SBMU硬件版本号最低字节Byte1对应的ASCII码";
CM_ SG_ 2416242301 S2P_Cfg3_HW_Ver_Byte2_61 "SBMU硬件版本号Byte2对应的ASCII码";
CM_ SG_ 2416242301 S2P_Cfg3_HW_Ver_Byte3_61 "SBMU硬件版本号Byte3对应的ASCII码";
CM_ SG_ 2416242301 S2P_Cfg3_HW_Ver_Byte4_61 "SBMU硬件版本号Byte4对应的ASCII码";
CM_ SG_ 2416242301 S2P_Cfg3_HW_Ver_Byte5_61 "SBMU硬件版本号Byte5对应的ASCII码";
CM_ SG_ 2416242301 S2P_Cfg3_HW_Ver_Byte6_61 "SBMU硬件版本号Byte6对应的ASCII码";
CM_ SG_ 2416242301 S2P_Cfg3_HW_Ver_Byte7_61 "SBMU硬件版本号Byte7对应的ASCII码";
CM_ SG_ 2416242301 S2P_Cfg3_HW_Ver_Byte8_61 "SBMU硬件版本号Byte8对应的ASCII码";
CM_ SG_ 2416242302 S2P_Cfg3_HW_Ver_Byte1_62 "SBMU硬件版本号最低字节Byte1对应的ASCII码";
CM_ SG_ 2416242302 S2P_Cfg3_HW_Ver_Byte2_62 "SBMU硬件版本号Byte2对应的ASCII码";
CM_ SG_ 2416242302 S2P_Cfg3_HW_Ver_Byte3_62 "SBMU硬件版本号Byte3对应的ASCII码";
CM_ SG_ 2416242302 S2P_Cfg3_HW_Ver_Byte4_62 "SBMU硬件版本号Byte4对应的ASCII码";
CM_ SG_ 2416242302 S2P_Cfg3_HW_Ver_Byte5_62 "SBMU硬件版本号Byte5对应的ASCII码";
CM_ SG_ 2416242302 S2P_Cfg3_HW_Ver_Byte6_62 "SBMU硬件版本号Byte6对应的ASCII码";
CM_ SG_ 2416242302 S2P_Cfg3_HW_Ver_Byte7_62 "SBMU硬件版本号Byte7对应的ASCII码";
CM_ SG_ 2416242302 S2P_Cfg3_HW_Ver_Byte8_62 "SBMU硬件版本号Byte8对应的ASCII码";
CM_ SG_ 2416242303 S2P_Cfg3_HW_Ver_Byte1_63 "SBMU硬件版本号最低字节Byte1对应的ASCII码";
CM_ SG_ 2416242303 S2P_Cfg3_HW_Ver_Byte2_63 "SBMU硬件版本号Byte2对应的ASCII码";
CM_ SG_ 2416242303 S2P_Cfg3_HW_Ver_Byte3_63 "SBMU硬件版本号Byte3对应的ASCII码";
CM_ SG_ 2416242303 S2P_Cfg3_HW_Ver_Byte4_63 "SBMU硬件版本号Byte4对应的ASCII码";
CM_ SG_ 2416242303 S2P_Cfg3_HW_Ver_Byte5_63 "SBMU硬件版本号Byte5对应的ASCII码";
CM_ SG_ 2416242303 S2P_Cfg3_HW_Ver_Byte6_63 "SBMU硬件版本号Byte6对应的ASCII码";
CM_ SG_ 2416242303 S2P_Cfg3_HW_Ver_Byte7_63 "SBMU硬件版本号Byte7对应的ASCII码";
CM_ SG_ 2416242303 S2P_Cfg3_HW_Ver_Byte8_63 "SBMU硬件版本号Byte8对应的ASCII码";
CM_ SG_ 2416307777 S2P_Cfg4_HW_Ver_Byte9_01 "SBMU硬件版本号Byte9对应的ASCII码";
CM_ SG_ 2416307777 S2P_Cfg4_HW_Ver_Byte10_01 "SBMU硬件版本号Byte10对应的ASCII码";
CM_ SG_ 2416307777 S2P_Cfg4_HW_Ver_Byte11_01 "SBMU硬件版本号Byte11对应的ASCII码";
CM_ SG_ 2416307777 S2P_Cfg4_HW_Ver_Byte12_01 "SBMU硬件版本号Byte12对应的ASCII码";
CM_ SG_ 2416307777 S2P_Cfg4_HW_Ver_Byte13_01 "SBMU硬件版本号Byte13对应的ASCII码";
CM_ SG_ 2416307777 S2P_Cfg4_HW_Ver_Byte14_01 "SBMU硬件版本号Byte14对应的ASCII码";
CM_ SG_ 2416307777 S2P_Cfg4_HW_Ver_Byte15_01 "SBMU硬件版本号Byte15对应的ASCII码";
CM_ SG_ 2416307777 S2P_Cfg4_HW_Ver_Byte16_01 "SBMU硬件版本号最高字节Byte16对应的ASCII码";
CM_ SG_ 2416307778 S2P_Cfg4_HW_Ver_Byte9_02 "SBMU硬件版本号Byte9对应的ASCII码";
CM_ SG_ 2416307778 S2P_Cfg4_HW_Ver_Byte10_02 "SBMU硬件版本号Byte10对应的ASCII码";
CM_ SG_ 2416307778 S2P_Cfg4_HW_Ver_Byte11_02 "SBMU硬件版本号Byte11对应的ASCII码";
CM_ SG_ 2416307778 S2P_Cfg4_HW_Ver_Byte12_02 "SBMU硬件版本号Byte12对应的ASCII码";
CM_ SG_ 2416307778 S2P_Cfg4_HW_Ver_Byte13_02 "SBMU硬件版本号Byte13对应的ASCII码";
CM_ SG_ 2416307778 S2P_Cfg4_HW_Ver_Byte14_02 "SBMU硬件版本号Byte14对应的ASCII码";
CM_ SG_ 2416307778 S2P_Cfg4_HW_Ver_Byte15_02 "SBMU硬件版本号Byte15对应的ASCII码";
CM_ SG_ 2416307778 S2P_Cfg4_HW_Ver_Byte16_02 "SBMU硬件版本号最高字节Byte16对应的ASCII码";
CM_ SG_ 2416307779 S2P_Cfg4_HW_Ver_Byte9_03 "SBMU硬件版本号Byte9对应的ASCII码";
CM_ SG_ 2416307779 S2P_Cfg4_HW_Ver_Byte10_03 "SBMU硬件版本号Byte10对应的ASCII码";
CM_ SG_ 2416307779 S2P_Cfg4_HW_Ver_Byte11_03 "SBMU硬件版本号Byte11对应的ASCII码";
CM_ SG_ 2416307779 S2P_Cfg4_HW_Ver_Byte12_03 "SBMU硬件版本号Byte12对应的ASCII码";
CM_ SG_ 2416307779 S2P_Cfg4_HW_Ver_Byte13_03 "SBMU硬件版本号Byte13对应的ASCII码";
CM_ SG_ 2416307779 S2P_Cfg4_HW_Ver_Byte14_03 "SBMU硬件版本号Byte14对应的ASCII码";
CM_ SG_ 2416307779 S2P_Cfg4_HW_Ver_Byte15_03 "SBMU硬件版本号Byte15对应的ASCII码";
CM_ SG_ 2416307779 S2P_Cfg4_HW_Ver_Byte16_03 "SBMU硬件版本号最高字节Byte16对应的ASCII码";
CM_ SG_ 2416307780 S2P_Cfg4_HW_Ver_Byte9_04 "SBMU硬件版本号Byte9对应的ASCII码";
CM_ SG_ 2416307780 S2P_Cfg4_HW_Ver_Byte10_04 "SBMU硬件版本号Byte10对应的ASCII码";
CM_ SG_ 2416307780 S2P_Cfg4_HW_Ver_Byte11_04 "SBMU硬件版本号Byte11对应的ASCII码";
CM_ SG_ 2416307780 S2P_Cfg4_HW_Ver_Byte12_04 "SBMU硬件版本号Byte12对应的ASCII码";
CM_ SG_ 2416307780 S2P_Cfg4_HW_Ver_Byte13_04 "SBMU硬件版本号Byte13对应的ASCII码";
CM_ SG_ 2416307780 S2P_Cfg4_HW_Ver_Byte14_04 "SBMU硬件版本号Byte14对应的ASCII码";
CM_ SG_ 2416307780 S2P_Cfg4_HW_Ver_Byte15_04 "SBMU硬件版本号Byte15对应的ASCII码";
CM_ SG_ 2416307780 S2P_Cfg4_HW_Ver_Byte16_04 "SBMU硬件版本号最高字节Byte16对应的ASCII码";
CM_ SG_ 2416307781 S2P_Cfg4_HW_Ver_Byte9_05 "SBMU硬件版本号Byte9对应的ASCII码";
CM_ SG_ 2416307781 S2P_Cfg4_HW_Ver_Byte10_05 "SBMU硬件版本号Byte10对应的ASCII码";
CM_ SG_ 2416307781 S2P_Cfg4_HW_Ver_Byte11_05 "SBMU硬件版本号Byte11对应的ASCII码";
CM_ SG_ 2416307781 S2P_Cfg4_HW_Ver_Byte12_05 "SBMU硬件版本号Byte12对应的ASCII码";
CM_ SG_ 2416307781 S2P_Cfg4_HW_Ver_Byte13_05 "SBMU硬件版本号Byte13对应的ASCII码";
CM_ SG_ 2416307781 S2P_Cfg4_HW_Ver_Byte14_05 "SBMU硬件版本号Byte14对应的ASCII码";
CM_ SG_ 2416307781 S2P_Cfg4_HW_Ver_Byte15_05 "SBMU硬件版本号Byte15对应的ASCII码";
CM_ SG_ 2416307781 S2P_Cfg4_HW_Ver_Byte16_05 "SBMU硬件版本号最高字节Byte16对应的ASCII码";
CM_ SG_ 2416307782 S2P_Cfg4_HW_Ver_Byte9_06 "SBMU硬件版本号Byte9对应的ASCII码";
CM_ SG_ 2416307782 S2P_Cfg4_HW_Ver_Byte10_06 "SBMU硬件版本号Byte10对应的ASCII码";
CM_ SG_ 2416307782 S2P_Cfg4_HW_Ver_Byte11_06 "SBMU硬件版本号Byte11对应的ASCII码";
CM_ SG_ 2416307782 S2P_Cfg4_HW_Ver_Byte12_06 "SBMU硬件版本号Byte12对应的ASCII码";
CM_ SG_ 2416307782 S2P_Cfg4_HW_Ver_Byte13_06 "SBMU硬件版本号Byte13对应的ASCII码";
CM_ SG_ 2416307782 S2P_Cfg4_HW_Ver_Byte14_06 "SBMU硬件版本号Byte14对应的ASCII码";
CM_ SG_ 2416307782 S2P_Cfg4_HW_Ver_Byte15_06 "SBMU硬件版本号Byte15对应的ASCII码";
CM_ SG_ 2416307782 S2P_Cfg4_HW_Ver_Byte16_06 "SBMU硬件版本号最高字节Byte16对应的ASCII码";
CM_ SG_ 2416307783 S2P_Cfg4_HW_Ver_Byte9_07 "SBMU硬件版本号Byte9对应的ASCII码";
CM_ SG_ 2416307783 S2P_Cfg4_HW_Ver_Byte10_07 "SBMU硬件版本号Byte10对应的ASCII码";
CM_ SG_ 2416307783 S2P_Cfg4_HW_Ver_Byte11_07 "SBMU硬件版本号Byte11对应的ASCII码";
CM_ SG_ 2416307783 S2P_Cfg4_HW_Ver_Byte12_07 "SBMU硬件版本号Byte12对应的ASCII码";
CM_ SG_ 2416307783 S2P_Cfg4_HW_Ver_Byte13_07 "SBMU硬件版本号Byte13对应的ASCII码";
CM_ SG_ 2416307783 S2P_Cfg4_HW_Ver_Byte14_07 "SBMU硬件版本号Byte14对应的ASCII码";
CM_ SG_ 2416307783 S2P_Cfg4_HW_Ver_Byte15_07 "SBMU硬件版本号Byte15对应的ASCII码";
CM_ SG_ 2416307783 S2P_Cfg4_HW_Ver_Byte16_07 "SBMU硬件版本号最高字节Byte16对应的ASCII码";
CM_ SG_ 2416307784 S2P_Cfg4_HW_Ver_Byte9_08 "SBMU硬件版本号Byte9对应的ASCII码";
CM_ SG_ 2416307784 S2P_Cfg4_HW_Ver_Byte10_08 "SBMU硬件版本号Byte10对应的ASCII码";
CM_ SG_ 2416307784 S2P_Cfg4_HW_Ver_Byte11_08 "SBMU硬件版本号Byte11对应的ASCII码";
CM_ SG_ 2416307784 S2P_Cfg4_HW_Ver_Byte12_08 "SBMU硬件版本号Byte12对应的ASCII码";
CM_ SG_ 2416307784 S2P_Cfg4_HW_Ver_Byte13_08 "SBMU硬件版本号Byte13对应的ASCII码";
CM_ SG_ 2416307784 S2P_Cfg4_HW_Ver_Byte14_08 "SBMU硬件版本号Byte14对应的ASCII码";
CM_ SG_ 2416307784 S2P_Cfg4_HW_Ver_Byte15_08 "SBMU硬件版本号Byte15对应的ASCII码";
CM_ SG_ 2416307784 S2P_Cfg4_HW_Ver_Byte16_08 "SBMU硬件版本号最高字节Byte16对应的ASCII码";
CM_ SG_ 2416307785 S2P_Cfg4_HW_Ver_Byte9_09 "SBMU硬件版本号Byte9对应的ASCII码";
CM_ SG_ 2416307785 S2P_Cfg4_HW_Ver_Byte10_09 "SBMU硬件版本号Byte10对应的ASCII码";
CM_ SG_ 2416307785 S2P_Cfg4_HW_Ver_Byte11_09 "SBMU硬件版本号Byte11对应的ASCII码";
CM_ SG_ 2416307785 S2P_Cfg4_HW_Ver_Byte12_09 "SBMU硬件版本号Byte12对应的ASCII码";
CM_ SG_ 2416307785 S2P_Cfg4_HW_Ver_Byte13_09 "SBMU硬件版本号Byte13对应的ASCII码";
CM_ SG_ 2416307785 S2P_Cfg4_HW_Ver_Byte14_09 "SBMU硬件版本号Byte14对应的ASCII码";
CM_ SG_ 2416307785 S2P_Cfg4_HW_Ver_Byte15_09 "SBMU硬件版本号Byte15对应的ASCII码";
CM_ SG_ 2416307785 S2P_Cfg4_HW_Ver_Byte16_09 "SBMU硬件版本号最高字节Byte16对应的ASCII码";
CM_ SG_ 2416307786 S2P_Cfg4_HW_Ver_Byte9_10 "SBMU硬件版本号Byte9对应的ASCII码";
CM_ SG_ 2416307786 S2P_Cfg4_HW_Ver_Byte10_10 "SBMU硬件版本号Byte10对应的ASCII码";
CM_ SG_ 2416307786 S2P_Cfg4_HW_Ver_Byte11_10 "SBMU硬件版本号Byte11对应的ASCII码";
CM_ SG_ 2416307786 S2P_Cfg4_HW_Ver_Byte12_10 "SBMU硬件版本号Byte12对应的ASCII码";
CM_ SG_ 2416307786 S2P_Cfg4_HW_Ver_Byte13_10 "SBMU硬件版本号Byte13对应的ASCII码";
CM_ SG_ 2416307786 S2P_Cfg4_HW_Ver_Byte14_10 "SBMU硬件版本号Byte14对应的ASCII码";
CM_ SG_ 2416307786 S2P_Cfg4_HW_Ver_Byte15_10 "SBMU硬件版本号Byte15对应的ASCII码";
CM_ SG_ 2416307786 S2P_Cfg4_HW_Ver_Byte16_10 "SBMU硬件版本号最高字节Byte16对应的ASCII码";
CM_ SG_ 2416307787 S2P_Cfg4_HW_Ver_Byte9_11 "SBMU硬件版本号Byte9对应的ASCII码";
CM_ SG_ 2416307787 S2P_Cfg4_HW_Ver_Byte10_11 "SBMU硬件版本号Byte10对应的ASCII码";
CM_ SG_ 2416307787 S2P_Cfg4_HW_Ver_Byte11_11 "SBMU硬件版本号Byte11对应的ASCII码";
CM_ SG_ 2416307787 S2P_Cfg4_HW_Ver_Byte12_11 "SBMU硬件版本号Byte12对应的ASCII码";
CM_ SG_ 2416307787 S2P_Cfg4_HW_Ver_Byte13_11 "SBMU硬件版本号Byte13对应的ASCII码";
CM_ SG_ 2416307787 S2P_Cfg4_HW_Ver_Byte14_11 "SBMU硬件版本号Byte14对应的ASCII码";
CM_ SG_ 2416307787 S2P_Cfg4_HW_Ver_Byte15_11 "SBMU硬件版本号Byte15对应的ASCII码";
CM_ SG_ 2416307787 S2P_Cfg4_HW_Ver_Byte16_11 "SBMU硬件版本号最高字节Byte16对应的ASCII码";
CM_ SG_ 2416307788 S2P_Cfg4_HW_Ver_Byte9_12 "SBMU硬件版本号Byte9对应的ASCII码";
CM_ SG_ 2416307788 S2P_Cfg4_HW_Ver_Byte10_12 "SBMU硬件版本号Byte10对应的ASCII码";
CM_ SG_ 2416307788 S2P_Cfg4_HW_Ver_Byte11_12 "SBMU硬件版本号Byte11对应的ASCII码";
CM_ SG_ 2416307788 S2P_Cfg4_HW_Ver_Byte12_12 "SBMU硬件版本号Byte12对应的ASCII码";
CM_ SG_ 2416307788 S2P_Cfg4_HW_Ver_Byte13_12 "SBMU硬件版本号Byte13对应的ASCII码";
CM_ SG_ 2416307788 S2P_Cfg4_HW_Ver_Byte14_12 "SBMU硬件版本号Byte14对应的ASCII码";
CM_ SG_ 2416307788 S2P_Cfg4_HW_Ver_Byte15_12 "SBMU硬件版本号Byte15对应的ASCII码";
CM_ SG_ 2416307788 S2P_Cfg4_HW_Ver_Byte16_12 "SBMU硬件版本号最高字节Byte16对应的ASCII码";
CM_ SG_ 2416307789 S2P_Cfg4_HW_Ver_Byte9_13 "SBMU硬件版本号Byte9对应的ASCII码";
CM_ SG_ 2416307789 S2P_Cfg4_HW_Ver_Byte10_13 "SBMU硬件版本号Byte10对应的ASCII码";
CM_ SG_ 2416307789 S2P_Cfg4_HW_Ver_Byte11_13 "SBMU硬件版本号Byte11对应的ASCII码";
CM_ SG_ 2416307789 S2P_Cfg4_HW_Ver_Byte12_13 "SBMU硬件版本号Byte12对应的ASCII码";
CM_ SG_ 2416307789 S2P_Cfg4_HW_Ver_Byte13_13 "SBMU硬件版本号Byte13对应的ASCII码";
CM_ SG_ 2416307789 S2P_Cfg4_HW_Ver_Byte14_13 "SBMU硬件版本号Byte14对应的ASCII码";
CM_ SG_ 2416307789 S2P_Cfg4_HW_Ver_Byte15_13 "SBMU硬件版本号Byte15对应的ASCII码";
CM_ SG_ 2416307789 S2P_Cfg4_HW_Ver_Byte16_13 "SBMU硬件版本号最高字节Byte16对应的ASCII码";
CM_ SG_ 2416307790 S2P_Cfg4_HW_Ver_Byte9_14 "SBMU硬件版本号Byte9对应的ASCII码";
CM_ SG_ 2416307790 S2P_Cfg4_HW_Ver_Byte10_14 "SBMU硬件版本号Byte10对应的ASCII码";
CM_ SG_ 2416307790 S2P_Cfg4_HW_Ver_Byte11_14 "SBMU硬件版本号Byte11对应的ASCII码";
CM_ SG_ 2416307790 S2P_Cfg4_HW_Ver_Byte12_14 "SBMU硬件版本号Byte12对应的ASCII码";
CM_ SG_ 2416307790 S2P_Cfg4_HW_Ver_Byte13_14 "SBMU硬件版本号Byte13对应的ASCII码";
CM_ SG_ 2416307790 S2P_Cfg4_HW_Ver_Byte14_14 "SBMU硬件版本号Byte14对应的ASCII码";
CM_ SG_ 2416307790 S2P_Cfg4_HW_Ver_Byte15_14 "SBMU硬件版本号Byte15对应的ASCII码";
CM_ SG_ 2416307790 S2P_Cfg4_HW_Ver_Byte16_14 "SBMU硬件版本号最高字节Byte16对应的ASCII码";
CM_ SG_ 2416307791 S2P_Cfg4_HW_Ver_Byte9_15 "SBMU硬件版本号Byte9对应的ASCII码";
CM_ SG_ 2416307791 S2P_Cfg4_HW_Ver_Byte10_15 "SBMU硬件版本号Byte10对应的ASCII码";
CM_ SG_ 2416307791 S2P_Cfg4_HW_Ver_Byte11_15 "SBMU硬件版本号Byte11对应的ASCII码";
CM_ SG_ 2416307791 S2P_Cfg4_HW_Ver_Byte12_15 "SBMU硬件版本号Byte12对应的ASCII码";
CM_ SG_ 2416307791 S2P_Cfg4_HW_Ver_Byte13_15 "SBMU硬件版本号Byte13对应的ASCII码";
CM_ SG_ 2416307791 S2P_Cfg4_HW_Ver_Byte14_15 "SBMU硬件版本号Byte14对应的ASCII码";
CM_ SG_ 2416307791 S2P_Cfg4_HW_Ver_Byte15_15 "SBMU硬件版本号Byte15对应的ASCII码";
CM_ SG_ 2416307791 S2P_Cfg4_HW_Ver_Byte16_15 "SBMU硬件版本号最高字节Byte16对应的ASCII码";
CM_ SG_ 2416307792 S2P_Cfg4_HW_Ver_Byte9_16 "SBMU硬件版本号Byte9对应的ASCII码";
CM_ SG_ 2416307792 S2P_Cfg4_HW_Ver_Byte10_16 "SBMU硬件版本号Byte10对应的ASCII码";
CM_ SG_ 2416307792 S2P_Cfg4_HW_Ver_Byte11_16 "SBMU硬件版本号Byte11对应的ASCII码";
CM_ SG_ 2416307792 S2P_Cfg4_HW_Ver_Byte12_16 "SBMU硬件版本号Byte12对应的ASCII码";
CM_ SG_ 2416307792 S2P_Cfg4_HW_Ver_Byte13_16 "SBMU硬件版本号Byte13对应的ASCII码";
CM_ SG_ 2416307792 S2P_Cfg4_HW_Ver_Byte14_16 "SBMU硬件版本号Byte14对应的ASCII码";
CM_ SG_ 2416307792 S2P_Cfg4_HW_Ver_Byte15_16 "SBMU硬件版本号Byte15对应的ASCII码";
CM_ SG_ 2416307792 S2P_Cfg4_HW_Ver_Byte16_16 "SBMU硬件版本号最高字节Byte16对应的ASCII码";
CM_ SG_ 2416307793 S2P_Cfg4_HW_Ver_Byte9_17 "SBMU硬件版本号Byte9对应的ASCII码";
CM_ SG_ 2416307793 S2P_Cfg4_HW_Ver_Byte10_17 "SBMU硬件版本号Byte10对应的ASCII码";
CM_ SG_ 2416307793 S2P_Cfg4_HW_Ver_Byte11_17 "SBMU硬件版本号Byte11对应的ASCII码";
CM_ SG_ 2416307793 S2P_Cfg4_HW_Ver_Byte12_17 "SBMU硬件版本号Byte12对应的ASCII码";
CM_ SG_ 2416307793 S2P_Cfg4_HW_Ver_Byte13_17 "SBMU硬件版本号Byte13对应的ASCII码";
CM_ SG_ 2416307793 S2P_Cfg4_HW_Ver_Byte14_17 "SBMU硬件版本号Byte14对应的ASCII码";
CM_ SG_ 2416307793 S2P_Cfg4_HW_Ver_Byte15_17 "SBMU硬件版本号Byte15对应的ASCII码";
CM_ SG_ 2416307793 S2P_Cfg4_HW_Ver_Byte16_17 "SBMU硬件版本号最高字节Byte16对应的ASCII码";
CM_ SG_ 2416307794 S2P_Cfg4_HW_Ver_Byte9_18 "SBMU硬件版本号Byte9对应的ASCII码";
CM_ SG_ 2416307794 S2P_Cfg4_HW_Ver_Byte10_18 "SBMU硬件版本号Byte10对应的ASCII码";
CM_ SG_ 2416307794 S2P_Cfg4_HW_Ver_Byte11_18 "SBMU硬件版本号Byte11对应的ASCII码";
CM_ SG_ 2416307794 S2P_Cfg4_HW_Ver_Byte12_18 "SBMU硬件版本号Byte12对应的ASCII码";
CM_ SG_ 2416307794 S2P_Cfg4_HW_Ver_Byte13_18 "SBMU硬件版本号Byte13对应的ASCII码";
CM_ SG_ 2416307794 S2P_Cfg4_HW_Ver_Byte14_18 "SBMU硬件版本号Byte14对应的ASCII码";
CM_ SG_ 2416307794 S2P_Cfg4_HW_Ver_Byte15_18 "SBMU硬件版本号Byte15对应的ASCII码";
CM_ SG_ 2416307794 S2P_Cfg4_HW_Ver_Byte16_18 "SBMU硬件版本号最高字节Byte16对应的ASCII码";
CM_ SG_ 2416307795 S2P_Cfg4_HW_Ver_Byte9_19 "SBMU硬件版本号Byte9对应的ASCII码";
CM_ SG_ 2416307795 S2P_Cfg4_HW_Ver_Byte10_19 "SBMU硬件版本号Byte10对应的ASCII码";
CM_ SG_ 2416307795 S2P_Cfg4_HW_Ver_Byte11_19 "SBMU硬件版本号Byte11对应的ASCII码";
CM_ SG_ 2416307795 S2P_Cfg4_HW_Ver_Byte12_19 "SBMU硬件版本号Byte12对应的ASCII码";
CM_ SG_ 2416307795 S2P_Cfg4_HW_Ver_Byte13_19 "SBMU硬件版本号Byte13对应的ASCII码";
CM_ SG_ 2416307795 S2P_Cfg4_HW_Ver_Byte14_19 "SBMU硬件版本号Byte14对应的ASCII码";
CM_ SG_ 2416307795 S2P_Cfg4_HW_Ver_Byte15_19 "SBMU硬件版本号Byte15对应的ASCII码";
CM_ SG_ 2416307795 S2P_Cfg4_HW_Ver_Byte16_19 "SBMU硬件版本号最高字节Byte16对应的ASCII码";
CM_ SG_ 2416307796 S2P_Cfg4_HW_Ver_Byte9_20 "SBMU硬件版本号Byte9对应的ASCII码";
CM_ SG_ 2416307796 S2P_Cfg4_HW_Ver_Byte10_20 "SBMU硬件版本号Byte10对应的ASCII码";
CM_ SG_ 2416307796 S2P_Cfg4_HW_Ver_Byte11_20 "SBMU硬件版本号Byte11对应的ASCII码";
CM_ SG_ 2416307796 S2P_Cfg4_HW_Ver_Byte12_20 "SBMU硬件版本号Byte12对应的ASCII码";
CM_ SG_ 2416307796 S2P_Cfg4_HW_Ver_Byte13_20 "SBMU硬件版本号Byte13对应的ASCII码";
CM_ SG_ 2416307796 S2P_Cfg4_HW_Ver_Byte14_20 "SBMU硬件版本号Byte14对应的ASCII码";
CM_ SG_ 2416307796 S2P_Cfg4_HW_Ver_Byte15_20 "SBMU硬件版本号Byte15对应的ASCII码";
CM_ SG_ 2416307796 S2P_Cfg4_HW_Ver_Byte16_20 "SBMU硬件版本号最高字节Byte16对应的ASCII码";
CM_ SG_ 2416307797 S2P_Cfg4_HW_Ver_Byte9_21 "SBMU硬件版本号Byte9对应的ASCII码";
CM_ SG_ 2416307797 S2P_Cfg4_HW_Ver_Byte10_21 "SBMU硬件版本号Byte10对应的ASCII码";
CM_ SG_ 2416307797 S2P_Cfg4_HW_Ver_Byte11_21 "SBMU硬件版本号Byte11对应的ASCII码";
CM_ SG_ 2416307797 S2P_Cfg4_HW_Ver_Byte12_21 "SBMU硬件版本号Byte12对应的ASCII码";
CM_ SG_ 2416307797 S2P_Cfg4_HW_Ver_Byte13_21 "SBMU硬件版本号Byte13对应的ASCII码";
CM_ SG_ 2416307797 S2P_Cfg4_HW_Ver_Byte14_21 "SBMU硬件版本号Byte14对应的ASCII码";
CM_ SG_ 2416307797 S2P_Cfg4_HW_Ver_Byte15_21 "SBMU硬件版本号Byte15对应的ASCII码";
CM_ SG_ 2416307797 S2P_Cfg4_HW_Ver_Byte16_21 "SBMU硬件版本号最高字节Byte16对应的ASCII码";
CM_ SG_ 2416307798 S2P_Cfg4_HW_Ver_Byte9_22 "SBMU硬件版本号Byte9对应的ASCII码";
CM_ SG_ 2416307798 S2P_Cfg4_HW_Ver_Byte10_22 "SBMU硬件版本号Byte10对应的ASCII码";
CM_ SG_ 2416307798 S2P_Cfg4_HW_Ver_Byte11_22 "SBMU硬件版本号Byte11对应的ASCII码";
CM_ SG_ 2416307798 S2P_Cfg4_HW_Ver_Byte12_22 "SBMU硬件版本号Byte12对应的ASCII码";
CM_ SG_ 2416307798 S2P_Cfg4_HW_Ver_Byte13_22 "SBMU硬件版本号Byte13对应的ASCII码";
CM_ SG_ 2416307798 S2P_Cfg4_HW_Ver_Byte14_22 "SBMU硬件版本号Byte14对应的ASCII码";
CM_ SG_ 2416307798 S2P_Cfg4_HW_Ver_Byte15_22 "SBMU硬件版本号Byte15对应的ASCII码";
CM_ SG_ 2416307798 S2P_Cfg4_HW_Ver_Byte16_22 "SBMU硬件版本号最高字节Byte16对应的ASCII码";
CM_ SG_ 2416307799 S2P_Cfg4_HW_Ver_Byte9_23 "SBMU硬件版本号Byte9对应的ASCII码";
CM_ SG_ 2416307799 S2P_Cfg4_HW_Ver_Byte10_23 "SBMU硬件版本号Byte10对应的ASCII码";
CM_ SG_ 2416307799 S2P_Cfg4_HW_Ver_Byte11_23 "SBMU硬件版本号Byte11对应的ASCII码";
CM_ SG_ 2416307799 S2P_Cfg4_HW_Ver_Byte12_23 "SBMU硬件版本号Byte12对应的ASCII码";
CM_ SG_ 2416307799 S2P_Cfg4_HW_Ver_Byte13_23 "SBMU硬件版本号Byte13对应的ASCII码";
CM_ SG_ 2416307799 S2P_Cfg4_HW_Ver_Byte14_23 "SBMU硬件版本号Byte14对应的ASCII码";
CM_ SG_ 2416307799 S2P_Cfg4_HW_Ver_Byte15_23 "SBMU硬件版本号Byte15对应的ASCII码";
CM_ SG_ 2416307799 S2P_Cfg4_HW_Ver_Byte16_23 "SBMU硬件版本号最高字节Byte16对应的ASCII码";
CM_ SG_ 2416307800 S2P_Cfg4_HW_Ver_Byte9_24 "SBMU硬件版本号Byte9对应的ASCII码";
CM_ SG_ 2416307800 S2P_Cfg4_HW_Ver_Byte10_24 "SBMU硬件版本号Byte10对应的ASCII码";
CM_ SG_ 2416307800 S2P_Cfg4_HW_Ver_Byte11_24 "SBMU硬件版本号Byte11对应的ASCII码";
CM_ SG_ 2416307800 S2P_Cfg4_HW_Ver_Byte12_24 "SBMU硬件版本号Byte12对应的ASCII码";
CM_ SG_ 2416307800 S2P_Cfg4_HW_Ver_Byte13_24 "SBMU硬件版本号Byte13对应的ASCII码";
CM_ SG_ 2416307800 S2P_Cfg4_HW_Ver_Byte14_24 "SBMU硬件版本号Byte14对应的ASCII码";
CM_ SG_ 2416307800 S2P_Cfg4_HW_Ver_Byte15_24 "SBMU硬件版本号Byte15对应的ASCII码";
CM_ SG_ 2416307800 S2P_Cfg4_HW_Ver_Byte16_24 "SBMU硬件版本号最高字节Byte16对应的ASCII码";
CM_ SG_ 2416307801 S2P_Cfg4_HW_Ver_Byte9_25 "SBMU硬件版本号Byte9对应的ASCII码";
CM_ SG_ 2416307801 S2P_Cfg4_HW_Ver_Byte10_25 "SBMU硬件版本号Byte10对应的ASCII码";
CM_ SG_ 2416307801 S2P_Cfg4_HW_Ver_Byte11_25 "SBMU硬件版本号Byte11对应的ASCII码";
CM_ SG_ 2416307801 S2P_Cfg4_HW_Ver_Byte12_25 "SBMU硬件版本号Byte12对应的ASCII码";
CM_ SG_ 2416307801 S2P_Cfg4_HW_Ver_Byte13_25 "SBMU硬件版本号Byte13对应的ASCII码";
CM_ SG_ 2416307801 S2P_Cfg4_HW_Ver_Byte14_25 "SBMU硬件版本号Byte14对应的ASCII码";
CM_ SG_ 2416307801 S2P_Cfg4_HW_Ver_Byte15_25 "SBMU硬件版本号Byte15对应的ASCII码";
CM_ SG_ 2416307801 S2P_Cfg4_HW_Ver_Byte16_25 "SBMU硬件版本号最高字节Byte16对应的ASCII码";
CM_ SG_ 2416307802 S2P_Cfg4_HW_Ver_Byte9_26 "SBMU硬件版本号Byte9对应的ASCII码";
CM_ SG_ 2416307802 S2P_Cfg4_HW_Ver_Byte10_26 "SBMU硬件版本号Byte10对应的ASCII码";
CM_ SG_ 2416307802 S2P_Cfg4_HW_Ver_Byte11_26 "SBMU硬件版本号Byte11对应的ASCII码";
CM_ SG_ 2416307802 S2P_Cfg4_HW_Ver_Byte12_26 "SBMU硬件版本号Byte12对应的ASCII码";
CM_ SG_ 2416307802 S2P_Cfg4_HW_Ver_Byte13_26 "SBMU硬件版本号Byte13对应的ASCII码";
CM_ SG_ 2416307802 S2P_Cfg4_HW_Ver_Byte14_26 "SBMU硬件版本号Byte14对应的ASCII码";
CM_ SG_ 2416307802 S2P_Cfg4_HW_Ver_Byte15_26 "SBMU硬件版本号Byte15对应的ASCII码";
CM_ SG_ 2416307802 S2P_Cfg4_HW_Ver_Byte16_26 "SBMU硬件版本号最高字节Byte16对应的ASCII码";
CM_ SG_ 2416307803 S2P_Cfg4_HW_Ver_Byte9_27 "SBMU硬件版本号Byte9对应的ASCII码";
CM_ SG_ 2416307803 S2P_Cfg4_HW_Ver_Byte10_27 "SBMU硬件版本号Byte10对应的ASCII码";
CM_ SG_ 2416307803 S2P_Cfg4_HW_Ver_Byte11_27 "SBMU硬件版本号Byte11对应的ASCII码";
CM_ SG_ 2416307803 S2P_Cfg4_HW_Ver_Byte12_27 "SBMU硬件版本号Byte12对应的ASCII码";
CM_ SG_ 2416307803 S2P_Cfg4_HW_Ver_Byte13_27 "SBMU硬件版本号Byte13对应的ASCII码";
CM_ SG_ 2416307803 S2P_Cfg4_HW_Ver_Byte14_27 "SBMU硬件版本号Byte14对应的ASCII码";
CM_ SG_ 2416307803 S2P_Cfg4_HW_Ver_Byte15_27 "SBMU硬件版本号Byte15对应的ASCII码";
CM_ SG_ 2416307803 S2P_Cfg4_HW_Ver_Byte16_27 "SBMU硬件版本号最高字节Byte16对应的ASCII码";
CM_ SG_ 2416307804 S2P_Cfg4_HW_Ver_Byte9_28 "SBMU硬件版本号Byte9对应的ASCII码";
CM_ SG_ 2416307804 S2P_Cfg4_HW_Ver_Byte10_28 "SBMU硬件版本号Byte10对应的ASCII码";
CM_ SG_ 2416307804 S2P_Cfg4_HW_Ver_Byte11_28 "SBMU硬件版本号Byte11对应的ASCII码";
CM_ SG_ 2416307804 S2P_Cfg4_HW_Ver_Byte12_28 "SBMU硬件版本号Byte12对应的ASCII码";
CM_ SG_ 2416307804 S2P_Cfg4_HW_Ver_Byte13_28 "SBMU硬件版本号Byte13对应的ASCII码";
CM_ SG_ 2416307804 S2P_Cfg4_HW_Ver_Byte14_28 "SBMU硬件版本号Byte14对应的ASCII码";
CM_ SG_ 2416307804 S2P_Cfg4_HW_Ver_Byte15_28 "SBMU硬件版本号Byte15对应的ASCII码";
CM_ SG_ 2416307804 S2P_Cfg4_HW_Ver_Byte16_28 "SBMU硬件版本号最高字节Byte16对应的ASCII码";
CM_ SG_ 2416307805 S2P_Cfg4_HW_Ver_Byte9_29 "SBMU硬件版本号Byte9对应的ASCII码";
CM_ SG_ 2416307805 S2P_Cfg4_HW_Ver_Byte10_29 "SBMU硬件版本号Byte10对应的ASCII码";
CM_ SG_ 2416307805 S2P_Cfg4_HW_Ver_Byte11_29 "SBMU硬件版本号Byte11对应的ASCII码";
CM_ SG_ 2416307805 S2P_Cfg4_HW_Ver_Byte12_29 "SBMU硬件版本号Byte12对应的ASCII码";
CM_ SG_ 2416307805 S2P_Cfg4_HW_Ver_Byte13_29 "SBMU硬件版本号Byte13对应的ASCII码";
CM_ SG_ 2416307805 S2P_Cfg4_HW_Ver_Byte14_29 "SBMU硬件版本号Byte14对应的ASCII码";
CM_ SG_ 2416307805 S2P_Cfg4_HW_Ver_Byte15_29 "SBMU硬件版本号Byte15对应的ASCII码";
CM_ SG_ 2416307805 S2P_Cfg4_HW_Ver_Byte16_29 "SBMU硬件版本号最高字节Byte16对应的ASCII码";
CM_ SG_ 2416307806 S2P_Cfg4_HW_Ver_Byte9_30 "SBMU硬件版本号Byte9对应的ASCII码";
CM_ SG_ 2416307806 S2P_Cfg4_HW_Ver_Byte10_30 "SBMU硬件版本号Byte10对应的ASCII码";
CM_ SG_ 2416307806 S2P_Cfg4_HW_Ver_Byte11_30 "SBMU硬件版本号Byte11对应的ASCII码";
CM_ SG_ 2416307806 S2P_Cfg4_HW_Ver_Byte12_30 "SBMU硬件版本号Byte12对应的ASCII码";
CM_ SG_ 2416307806 S2P_Cfg4_HW_Ver_Byte13_30 "SBMU硬件版本号Byte13对应的ASCII码";
CM_ SG_ 2416307806 S2P_Cfg4_HW_Ver_Byte14_30 "SBMU硬件版本号Byte14对应的ASCII码";
CM_ SG_ 2416307806 S2P_Cfg4_HW_Ver_Byte15_30 "SBMU硬件版本号Byte15对应的ASCII码";
CM_ SG_ 2416307806 S2P_Cfg4_HW_Ver_Byte16_30 "SBMU硬件版本号最高字节Byte16对应的ASCII码";
CM_ SG_ 2416307807 S2P_Cfg4_HW_Ver_Byte9_31 "SBMU硬件版本号Byte9对应的ASCII码";
CM_ SG_ 2416307807 S2P_Cfg4_HW_Ver_Byte10_31 "SBMU硬件版本号Byte10对应的ASCII码";
CM_ SG_ 2416307807 S2P_Cfg4_HW_Ver_Byte11_31 "SBMU硬件版本号Byte11对应的ASCII码";
CM_ SG_ 2416307807 S2P_Cfg4_HW_Ver_Byte12_31 "SBMU硬件版本号Byte12对应的ASCII码";
CM_ SG_ 2416307807 S2P_Cfg4_HW_Ver_Byte13_31 "SBMU硬件版本号Byte13对应的ASCII码";
CM_ SG_ 2416307807 S2P_Cfg4_HW_Ver_Byte14_31 "SBMU硬件版本号Byte14对应的ASCII码";
CM_ SG_ 2416307807 S2P_Cfg4_HW_Ver_Byte15_31 "SBMU硬件版本号Byte15对应的ASCII码";
CM_ SG_ 2416307807 S2P_Cfg4_HW_Ver_Byte16_31 "SBMU硬件版本号最高字节Byte16对应的ASCII码";
CM_ SG_ 2416307808 S2P_Cfg4_HW_Ver_Byte9_32 "SBMU硬件版本号Byte9对应的ASCII码";
CM_ SG_ 2416307808 S2P_Cfg4_HW_Ver_Byte10_32 "SBMU硬件版本号Byte10对应的ASCII码";
CM_ SG_ 2416307808 S2P_Cfg4_HW_Ver_Byte11_32 "SBMU硬件版本号Byte11对应的ASCII码";
CM_ SG_ 2416307808 S2P_Cfg4_HW_Ver_Byte12_32 "SBMU硬件版本号Byte12对应的ASCII码";
CM_ SG_ 2416307808 S2P_Cfg4_HW_Ver_Byte13_32 "SBMU硬件版本号Byte13对应的ASCII码";
CM_ SG_ 2416307808 S2P_Cfg4_HW_Ver_Byte14_32 "SBMU硬件版本号Byte14对应的ASCII码";
CM_ SG_ 2416307808 S2P_Cfg4_HW_Ver_Byte15_32 "SBMU硬件版本号Byte15对应的ASCII码";
CM_ SG_ 2416307808 S2P_Cfg4_HW_Ver_Byte16_32 "SBMU硬件版本号最高字节Byte16对应的ASCII码";
CM_ SG_ 2416307809 S2P_Cfg4_HW_Ver_Byte9_33 "SBMU硬件版本号Byte9对应的ASCII码";
CM_ SG_ 2416307809 S2P_Cfg4_HW_Ver_Byte10_33 "SBMU硬件版本号Byte10对应的ASCII码";
CM_ SG_ 2416307809 S2P_Cfg4_HW_Ver_Byte11_33 "SBMU硬件版本号Byte11对应的ASCII码";
CM_ SG_ 2416307809 S2P_Cfg4_HW_Ver_Byte12_33 "SBMU硬件版本号Byte12对应的ASCII码";
CM_ SG_ 2416307809 S2P_Cfg4_HW_Ver_Byte13_33 "SBMU硬件版本号Byte13对应的ASCII码";
CM_ SG_ 2416307809 S2P_Cfg4_HW_Ver_Byte14_33 "SBMU硬件版本号Byte14对应的ASCII码";
CM_ SG_ 2416307809 S2P_Cfg4_HW_Ver_Byte15_33 "SBMU硬件版本号Byte15对应的ASCII码";
CM_ SG_ 2416307809 S2P_Cfg4_HW_Ver_Byte16_33 "SBMU硬件版本号最高字节Byte16对应的ASCII码";
CM_ SG_ 2416307810 S2P_Cfg4_HW_Ver_Byte9_34 "SBMU硬件版本号Byte9对应的ASCII码";
CM_ SG_ 2416307810 S2P_Cfg4_HW_Ver_Byte10_34 "SBMU硬件版本号Byte10对应的ASCII码";
CM_ SG_ 2416307810 S2P_Cfg4_HW_Ver_Byte11_34 "SBMU硬件版本号Byte11对应的ASCII码";
CM_ SG_ 2416307810 S2P_Cfg4_HW_Ver_Byte12_34 "SBMU硬件版本号Byte12对应的ASCII码";
CM_ SG_ 2416307810 S2P_Cfg4_HW_Ver_Byte13_34 "SBMU硬件版本号Byte13对应的ASCII码";
CM_ SG_ 2416307810 S2P_Cfg4_HW_Ver_Byte14_34 "SBMU硬件版本号Byte14对应的ASCII码";
CM_ SG_ 2416307810 S2P_Cfg4_HW_Ver_Byte15_34 "SBMU硬件版本号Byte15对应的ASCII码";
CM_ SG_ 2416307810 S2P_Cfg4_HW_Ver_Byte16_34 "SBMU硬件版本号最高字节Byte16对应的ASCII码";
CM_ SG_ 2416307811 S2P_Cfg4_HW_Ver_Byte9_35 "SBMU硬件版本号Byte9对应的ASCII码";
CM_ SG_ 2416307811 S2P_Cfg4_HW_Ver_Byte10_35 "SBMU硬件版本号Byte10对应的ASCII码";
CM_ SG_ 2416307811 S2P_Cfg4_HW_Ver_Byte11_35 "SBMU硬件版本号Byte11对应的ASCII码";
CM_ SG_ 2416307811 S2P_Cfg4_HW_Ver_Byte12_35 "SBMU硬件版本号Byte12对应的ASCII码";
CM_ SG_ 2416307811 S2P_Cfg4_HW_Ver_Byte13_35 "SBMU硬件版本号Byte13对应的ASCII码";
CM_ SG_ 2416307811 S2P_Cfg4_HW_Ver_Byte14_35 "SBMU硬件版本号Byte14对应的ASCII码";
CM_ SG_ 2416307811 S2P_Cfg4_HW_Ver_Byte15_35 "SBMU硬件版本号Byte15对应的ASCII码";
CM_ SG_ 2416307811 S2P_Cfg4_HW_Ver_Byte16_35 "SBMU硬件版本号最高字节Byte16对应的ASCII码";
CM_ SG_ 2416307812 S2P_Cfg4_HW_Ver_Byte9_36 "SBMU硬件版本号Byte9对应的ASCII码";
CM_ SG_ 2416307812 S2P_Cfg4_HW_Ver_Byte10_36 "SBMU硬件版本号Byte10对应的ASCII码";
CM_ SG_ 2416307812 S2P_Cfg4_HW_Ver_Byte11_36 "SBMU硬件版本号Byte11对应的ASCII码";
CM_ SG_ 2416307812 S2P_Cfg4_HW_Ver_Byte12_36 "SBMU硬件版本号Byte12对应的ASCII码";
CM_ SG_ 2416307812 S2P_Cfg4_HW_Ver_Byte13_36 "SBMU硬件版本号Byte13对应的ASCII码";
CM_ SG_ 2416307812 S2P_Cfg4_HW_Ver_Byte14_36 "SBMU硬件版本号Byte14对应的ASCII码";
CM_ SG_ 2416307812 S2P_Cfg4_HW_Ver_Byte15_36 "SBMU硬件版本号Byte15对应的ASCII码";
CM_ SG_ 2416307812 S2P_Cfg4_HW_Ver_Byte16_36 "SBMU硬件版本号最高字节Byte16对应的ASCII码";
CM_ SG_ 2416307813 S2P_Cfg4_HW_Ver_Byte9_37 "SBMU硬件版本号Byte9对应的ASCII码";
CM_ SG_ 2416307813 S2P_Cfg4_HW_Ver_Byte10_37 "SBMU硬件版本号Byte10对应的ASCII码";
CM_ SG_ 2416307813 S2P_Cfg4_HW_Ver_Byte11_37 "SBMU硬件版本号Byte11对应的ASCII码";
CM_ SG_ 2416307813 S2P_Cfg4_HW_Ver_Byte12_37 "SBMU硬件版本号Byte12对应的ASCII码";
CM_ SG_ 2416307813 S2P_Cfg4_HW_Ver_Byte13_37 "SBMU硬件版本号Byte13对应的ASCII码";
CM_ SG_ 2416307813 S2P_Cfg4_HW_Ver_Byte14_37 "SBMU硬件版本号Byte14对应的ASCII码";
CM_ SG_ 2416307813 S2P_Cfg4_HW_Ver_Byte15_37 "SBMU硬件版本号Byte15对应的ASCII码";
CM_ SG_ 2416307813 S2P_Cfg4_HW_Ver_Byte16_37 "SBMU硬件版本号最高字节Byte16对应的ASCII码";
CM_ SG_ 2416307814 S2P_Cfg4_HW_Ver_Byte9_38 "SBMU硬件版本号Byte9对应的ASCII码";
CM_ SG_ 2416307814 S2P_Cfg4_HW_Ver_Byte10_38 "SBMU硬件版本号Byte10对应的ASCII码";
CM_ SG_ 2416307814 S2P_Cfg4_HW_Ver_Byte11_38 "SBMU硬件版本号Byte11对应的ASCII码";
CM_ SG_ 2416307814 S2P_Cfg4_HW_Ver_Byte12_38 "SBMU硬件版本号Byte12对应的ASCII码";
CM_ SG_ 2416307814 S2P_Cfg4_HW_Ver_Byte13_38 "SBMU硬件版本号Byte13对应的ASCII码";
CM_ SG_ 2416307814 S2P_Cfg4_HW_Ver_Byte14_38 "SBMU硬件版本号Byte14对应的ASCII码";
CM_ SG_ 2416307814 S2P_Cfg4_HW_Ver_Byte15_38 "SBMU硬件版本号Byte15对应的ASCII码";
CM_ SG_ 2416307814 S2P_Cfg4_HW_Ver_Byte16_38 "SBMU硬件版本号最高字节Byte16对应的ASCII码";
CM_ SG_ 2416307815 S2P_Cfg4_HW_Ver_Byte9_39 "SBMU硬件版本号Byte9对应的ASCII码";
CM_ SG_ 2416307815 S2P_Cfg4_HW_Ver_Byte10_39 "SBMU硬件版本号Byte10对应的ASCII码";
CM_ SG_ 2416307815 S2P_Cfg4_HW_Ver_Byte11_39 "SBMU硬件版本号Byte11对应的ASCII码";
CM_ SG_ 2416307815 S2P_Cfg4_HW_Ver_Byte12_39 "SBMU硬件版本号Byte12对应的ASCII码";
CM_ SG_ 2416307815 S2P_Cfg4_HW_Ver_Byte13_39 "SBMU硬件版本号Byte13对应的ASCII码";
CM_ SG_ 2416307815 S2P_Cfg4_HW_Ver_Byte14_39 "SBMU硬件版本号Byte14对应的ASCII码";
CM_ SG_ 2416307815 S2P_Cfg4_HW_Ver_Byte15_39 "SBMU硬件版本号Byte15对应的ASCII码";
CM_ SG_ 2416307815 S2P_Cfg4_HW_Ver_Byte16_39 "SBMU硬件版本号最高字节Byte16对应的ASCII码";
CM_ SG_ 2416307816 S2P_Cfg4_HW_Ver_Byte9_40 "SBMU硬件版本号Byte9对应的ASCII码";
CM_ SG_ 2416307816 S2P_Cfg4_HW_Ver_Byte10_40 "SBMU硬件版本号Byte10对应的ASCII码";
CM_ SG_ 2416307816 S2P_Cfg4_HW_Ver_Byte11_40 "SBMU硬件版本号Byte11对应的ASCII码";
CM_ SG_ 2416307816 S2P_Cfg4_HW_Ver_Byte12_40 "SBMU硬件版本号Byte12对应的ASCII码";
CM_ SG_ 2416307816 S2P_Cfg4_HW_Ver_Byte13_40 "SBMU硬件版本号Byte13对应的ASCII码";
CM_ SG_ 2416307816 S2P_Cfg4_HW_Ver_Byte14_40 "SBMU硬件版本号Byte14对应的ASCII码";
CM_ SG_ 2416307816 S2P_Cfg4_HW_Ver_Byte15_40 "SBMU硬件版本号Byte15对应的ASCII码";
CM_ SG_ 2416307816 S2P_Cfg4_HW_Ver_Byte16_40 "SBMU硬件版本号最高字节Byte16对应的ASCII码";
CM_ SG_ 2416307817 S2P_Cfg4_HW_Ver_Byte9_41 "SBMU硬件版本号Byte9对应的ASCII码";
CM_ SG_ 2416307817 S2P_Cfg4_HW_Ver_Byte10_41 "SBMU硬件版本号Byte10对应的ASCII码";
CM_ SG_ 2416307817 S2P_Cfg4_HW_Ver_Byte11_41 "SBMU硬件版本号Byte11对应的ASCII码";
CM_ SG_ 2416307817 S2P_Cfg4_HW_Ver_Byte12_41 "SBMU硬件版本号Byte12对应的ASCII码";
CM_ SG_ 2416307817 S2P_Cfg4_HW_Ver_Byte13_41 "SBMU硬件版本号Byte13对应的ASCII码";
CM_ SG_ 2416307817 S2P_Cfg4_HW_Ver_Byte14_41 "SBMU硬件版本号Byte14对应的ASCII码";
CM_ SG_ 2416307817 S2P_Cfg4_HW_Ver_Byte15_41 "SBMU硬件版本号Byte15对应的ASCII码";
CM_ SG_ 2416307817 S2P_Cfg4_HW_Ver_Byte16_41 "SBMU硬件版本号最高字节Byte16对应的ASCII码";
CM_ SG_ 2416307818 S2P_Cfg4_HW_Ver_Byte9_42 "SBMU硬件版本号Byte9对应的ASCII码";
CM_ SG_ 2416307818 S2P_Cfg4_HW_Ver_Byte10_42 "SBMU硬件版本号Byte10对应的ASCII码";
CM_ SG_ 2416307818 S2P_Cfg4_HW_Ver_Byte11_42 "SBMU硬件版本号Byte11对应的ASCII码";
CM_ SG_ 2416307818 S2P_Cfg4_HW_Ver_Byte12_42 "SBMU硬件版本号Byte12对应的ASCII码";
CM_ SG_ 2416307818 S2P_Cfg4_HW_Ver_Byte13_42 "SBMU硬件版本号Byte13对应的ASCII码";
CM_ SG_ 2416307818 S2P_Cfg4_HW_Ver_Byte14_42 "SBMU硬件版本号Byte14对应的ASCII码";
CM_ SG_ 2416307818 S2P_Cfg4_HW_Ver_Byte15_42 "SBMU硬件版本号Byte15对应的ASCII码";
CM_ SG_ 2416307818 S2P_Cfg4_HW_Ver_Byte16_42 "SBMU硬件版本号最高字节Byte16对应的ASCII码";
CM_ SG_ 2416307819 S2P_Cfg4_HW_Ver_Byte9_43 "SBMU硬件版本号Byte9对应的ASCII码";
CM_ SG_ 2416307819 S2P_Cfg4_HW_Ver_Byte10_43 "SBMU硬件版本号Byte10对应的ASCII码";
CM_ SG_ 2416307819 S2P_Cfg4_HW_Ver_Byte11_43 "SBMU硬件版本号Byte11对应的ASCII码";
CM_ SG_ 2416307819 S2P_Cfg4_HW_Ver_Byte12_43 "SBMU硬件版本号Byte12对应的ASCII码";
CM_ SG_ 2416307819 S2P_Cfg4_HW_Ver_Byte13_43 "SBMU硬件版本号Byte13对应的ASCII码";
CM_ SG_ 2416307819 S2P_Cfg4_HW_Ver_Byte14_43 "SBMU硬件版本号Byte14对应的ASCII码";
CM_ SG_ 2416307819 S2P_Cfg4_HW_Ver_Byte15_43 "SBMU硬件版本号Byte15对应的ASCII码";
CM_ SG_ 2416307819 S2P_Cfg4_HW_Ver_Byte16_43 "SBMU硬件版本号最高字节Byte16对应的ASCII码";
CM_ SG_ 2416307820 S2P_Cfg4_HW_Ver_Byte9_44 "SBMU硬件版本号Byte9对应的ASCII码";
CM_ SG_ 2416307820 S2P_Cfg4_HW_Ver_Byte10_44 "SBMU硬件版本号Byte10对应的ASCII码";
CM_ SG_ 2416307820 S2P_Cfg4_HW_Ver_Byte11_44 "SBMU硬件版本号Byte11对应的ASCII码";
CM_ SG_ 2416307820 S2P_Cfg4_HW_Ver_Byte12_44 "SBMU硬件版本号Byte12对应的ASCII码";
CM_ SG_ 2416307820 S2P_Cfg4_HW_Ver_Byte13_44 "SBMU硬件版本号Byte13对应的ASCII码";
CM_ SG_ 2416307820 S2P_Cfg4_HW_Ver_Byte14_44 "SBMU硬件版本号Byte14对应的ASCII码";
CM_ SG_ 2416307820 S2P_Cfg4_HW_Ver_Byte15_44 "SBMU硬件版本号Byte15对应的ASCII码";
CM_ SG_ 2416307820 S2P_Cfg4_HW_Ver_Byte16_44 "SBMU硬件版本号最高字节Byte16对应的ASCII码";
CM_ SG_ 2416307821 S2P_Cfg4_HW_Ver_Byte9_45 "SBMU硬件版本号Byte9对应的ASCII码";
CM_ SG_ 2416307821 S2P_Cfg4_HW_Ver_Byte10_45 "SBMU硬件版本号Byte10对应的ASCII码";
CM_ SG_ 2416307821 S2P_Cfg4_HW_Ver_Byte11_45 "SBMU硬件版本号Byte11对应的ASCII码";
CM_ SG_ 2416307821 S2P_Cfg4_HW_Ver_Byte12_45 "SBMU硬件版本号Byte12对应的ASCII码";
CM_ SG_ 2416307821 S2P_Cfg4_HW_Ver_Byte13_45 "SBMU硬件版本号Byte13对应的ASCII码";
CM_ SG_ 2416307821 S2P_Cfg4_HW_Ver_Byte14_45 "SBMU硬件版本号Byte14对应的ASCII码";
CM_ SG_ 2416307821 S2P_Cfg4_HW_Ver_Byte15_45 "SBMU硬件版本号Byte15对应的ASCII码";
CM_ SG_ 2416307821 S2P_Cfg4_HW_Ver_Byte16_45 "SBMU硬件版本号最高字节Byte16对应的ASCII码";
CM_ SG_ 2416307822 S2P_Cfg4_HW_Ver_Byte9_46 "SBMU硬件版本号Byte9对应的ASCII码";
CM_ SG_ 2416307822 S2P_Cfg4_HW_Ver_Byte10_46 "SBMU硬件版本号Byte10对应的ASCII码";
CM_ SG_ 2416307822 S2P_Cfg4_HW_Ver_Byte11_46 "SBMU硬件版本号Byte11对应的ASCII码";
CM_ SG_ 2416307822 S2P_Cfg4_HW_Ver_Byte12_46 "SBMU硬件版本号Byte12对应的ASCII码";
CM_ SG_ 2416307822 S2P_Cfg4_HW_Ver_Byte13_46 "SBMU硬件版本号Byte13对应的ASCII码";
CM_ SG_ 2416307822 S2P_Cfg4_HW_Ver_Byte14_46 "SBMU硬件版本号Byte14对应的ASCII码";
CM_ SG_ 2416307822 S2P_Cfg4_HW_Ver_Byte15_46 "SBMU硬件版本号Byte15对应的ASCII码";
CM_ SG_ 2416307822 S2P_Cfg4_HW_Ver_Byte16_46 "SBMU硬件版本号最高字节Byte16对应的ASCII码";
CM_ SG_ 2416307823 S2P_Cfg4_HW_Ver_Byte9_47 "SBMU硬件版本号Byte9对应的ASCII码";
CM_ SG_ 2416307823 S2P_Cfg4_HW_Ver_Byte10_47 "SBMU硬件版本号Byte10对应的ASCII码";
CM_ SG_ 2416307823 S2P_Cfg4_HW_Ver_Byte11_47 "SBMU硬件版本号Byte11对应的ASCII码";
CM_ SG_ 2416307823 S2P_Cfg4_HW_Ver_Byte12_47 "SBMU硬件版本号Byte12对应的ASCII码";
CM_ SG_ 2416307823 S2P_Cfg4_HW_Ver_Byte13_47 "SBMU硬件版本号Byte13对应的ASCII码";
CM_ SG_ 2416307823 S2P_Cfg4_HW_Ver_Byte14_47 "SBMU硬件版本号Byte14对应的ASCII码";
CM_ SG_ 2416307823 S2P_Cfg4_HW_Ver_Byte15_47 "SBMU硬件版本号Byte15对应的ASCII码";
CM_ SG_ 2416307823 S2P_Cfg4_HW_Ver_Byte16_47 "SBMU硬件版本号最高字节Byte16对应的ASCII码";
CM_ SG_ 2416307824 S2P_Cfg4_HW_Ver_Byte9_48 "SBMU硬件版本号Byte9对应的ASCII码";
CM_ SG_ 2416307824 S2P_Cfg4_HW_Ver_Byte10_48 "SBMU硬件版本号Byte10对应的ASCII码";
CM_ SG_ 2416307824 S2P_Cfg4_HW_Ver_Byte11_48 "SBMU硬件版本号Byte11对应的ASCII码";
CM_ SG_ 2416307824 S2P_Cfg4_HW_Ver_Byte12_48 "SBMU硬件版本号Byte12对应的ASCII码";
CM_ SG_ 2416307824 S2P_Cfg4_HW_Ver_Byte13_48 "SBMU硬件版本号Byte13对应的ASCII码";
CM_ SG_ 2416307824 S2P_Cfg4_HW_Ver_Byte14_48 "SBMU硬件版本号Byte14对应的ASCII码";
CM_ SG_ 2416307824 S2P_Cfg4_HW_Ver_Byte15_48 "SBMU硬件版本号Byte15对应的ASCII码";
CM_ SG_ 2416307824 S2P_Cfg4_HW_Ver_Byte16_48 "SBMU硬件版本号最高字节Byte16对应的ASCII码";
CM_ SG_ 2416307825 S2P_Cfg4_HW_Ver_Byte9_49 "SBMU硬件版本号Byte9对应的ASCII码";
CM_ SG_ 2416307825 S2P_Cfg4_HW_Ver_Byte10_49 "SBMU硬件版本号Byte10对应的ASCII码";
CM_ SG_ 2416307825 S2P_Cfg4_HW_Ver_Byte11_49 "SBMU硬件版本号Byte11对应的ASCII码";
CM_ SG_ 2416307825 S2P_Cfg4_HW_Ver_Byte12_49 "SBMU硬件版本号Byte12对应的ASCII码";
CM_ SG_ 2416307825 S2P_Cfg4_HW_Ver_Byte13_49 "SBMU硬件版本号Byte13对应的ASCII码";
CM_ SG_ 2416307825 S2P_Cfg4_HW_Ver_Byte14_49 "SBMU硬件版本号Byte14对应的ASCII码";
CM_ SG_ 2416307825 S2P_Cfg4_HW_Ver_Byte15_49 "SBMU硬件版本号Byte15对应的ASCII码";
CM_ SG_ 2416307825 S2P_Cfg4_HW_Ver_Byte16_49 "SBMU硬件版本号最高字节Byte16对应的ASCII码";
CM_ SG_ 2416307826 S2P_Cfg4_HW_Ver_Byte9_50 "SBMU硬件版本号Byte9对应的ASCII码";
CM_ SG_ 2416307826 S2P_Cfg4_HW_Ver_Byte10_50 "SBMU硬件版本号Byte10对应的ASCII码";
CM_ SG_ 2416307826 S2P_Cfg4_HW_Ver_Byte11_50 "SBMU硬件版本号Byte11对应的ASCII码";
CM_ SG_ 2416307826 S2P_Cfg4_HW_Ver_Byte12_50 "SBMU硬件版本号Byte12对应的ASCII码";
CM_ SG_ 2416307826 S2P_Cfg4_HW_Ver_Byte13_50 "SBMU硬件版本号Byte13对应的ASCII码";
CM_ SG_ 2416307826 S2P_Cfg4_HW_Ver_Byte14_50 "SBMU硬件版本号Byte14对应的ASCII码";
CM_ SG_ 2416307826 S2P_Cfg4_HW_Ver_Byte15_50 "SBMU硬件版本号Byte15对应的ASCII码";
CM_ SG_ 2416307826 S2P_Cfg4_HW_Ver_Byte16_50 "SBMU硬件版本号最高字节Byte16对应的ASCII码";
CM_ SG_ 2416307827 S2P_Cfg4_HW_Ver_Byte9_51 "SBMU硬件版本号Byte9对应的ASCII码";
CM_ SG_ 2416307827 S2P_Cfg4_HW_Ver_Byte10_51 "SBMU硬件版本号Byte10对应的ASCII码";
CM_ SG_ 2416307827 S2P_Cfg4_HW_Ver_Byte11_51 "SBMU硬件版本号Byte11对应的ASCII码";
CM_ SG_ 2416307827 S2P_Cfg4_HW_Ver_Byte12_51 "SBMU硬件版本号Byte12对应的ASCII码";
CM_ SG_ 2416307827 S2P_Cfg4_HW_Ver_Byte13_51 "SBMU硬件版本号Byte13对应的ASCII码";
CM_ SG_ 2416307827 S2P_Cfg4_HW_Ver_Byte14_51 "SBMU硬件版本号Byte14对应的ASCII码";
CM_ SG_ 2416307827 S2P_Cfg4_HW_Ver_Byte15_51 "SBMU硬件版本号Byte15对应的ASCII码";
CM_ SG_ 2416307827 S2P_Cfg4_HW_Ver_Byte16_51 "SBMU硬件版本号最高字节Byte16对应的ASCII码";
CM_ SG_ 2416307828 S2P_Cfg4_HW_Ver_Byte9_52 "SBMU硬件版本号Byte9对应的ASCII码";
CM_ SG_ 2416307828 S2P_Cfg4_HW_Ver_Byte10_52 "SBMU硬件版本号Byte10对应的ASCII码";
CM_ SG_ 2416307828 S2P_Cfg4_HW_Ver_Byte11_52 "SBMU硬件版本号Byte11对应的ASCII码";
CM_ SG_ 2416307828 S2P_Cfg4_HW_Ver_Byte12_52 "SBMU硬件版本号Byte12对应的ASCII码";
CM_ SG_ 2416307828 S2P_Cfg4_HW_Ver_Byte13_52 "SBMU硬件版本号Byte13对应的ASCII码";
CM_ SG_ 2416307828 S2P_Cfg4_HW_Ver_Byte14_52 "SBMU硬件版本号Byte14对应的ASCII码";
CM_ SG_ 2416307828 S2P_Cfg4_HW_Ver_Byte15_52 "SBMU硬件版本号Byte15对应的ASCII码";
CM_ SG_ 2416307828 S2P_Cfg4_HW_Ver_Byte16_52 "SBMU硬件版本号最高字节Byte16对应的ASCII码";
CM_ SG_ 2416307829 S2P_Cfg4_HW_Ver_Byte9_53 "SBMU硬件版本号Byte9对应的ASCII码";
CM_ SG_ 2416307829 S2P_Cfg4_HW_Ver_Byte10_53 "SBMU硬件版本号Byte10对应的ASCII码";
CM_ SG_ 2416307829 S2P_Cfg4_HW_Ver_Byte11_53 "SBMU硬件版本号Byte11对应的ASCII码";
CM_ SG_ 2416307829 S2P_Cfg4_HW_Ver_Byte12_53 "SBMU硬件版本号Byte12对应的ASCII码";
CM_ SG_ 2416307829 S2P_Cfg4_HW_Ver_Byte13_53 "SBMU硬件版本号Byte13对应的ASCII码";
CM_ SG_ 2416307829 S2P_Cfg4_HW_Ver_Byte14_53 "SBMU硬件版本号Byte14对应的ASCII码";
CM_ SG_ 2416307829 S2P_Cfg4_HW_Ver_Byte15_53 "SBMU硬件版本号Byte15对应的ASCII码";
CM_ SG_ 2416307829 S2P_Cfg4_HW_Ver_Byte16_53 "SBMU硬件版本号最高字节Byte16对应的ASCII码";
CM_ SG_ 2416307830 S2P_Cfg4_HW_Ver_Byte9_54 "SBMU硬件版本号Byte9对应的ASCII码";
CM_ SG_ 2416307830 S2P_Cfg4_HW_Ver_Byte10_54 "SBMU硬件版本号Byte10对应的ASCII码";
CM_ SG_ 2416307830 S2P_Cfg4_HW_Ver_Byte11_54 "SBMU硬件版本号Byte11对应的ASCII码";
CM_ SG_ 2416307830 S2P_Cfg4_HW_Ver_Byte12_54 "SBMU硬件版本号Byte12对应的ASCII码";
CM_ SG_ 2416307830 S2P_Cfg4_HW_Ver_Byte13_54 "SBMU硬件版本号Byte13对应的ASCII码";
CM_ SG_ 2416307830 S2P_Cfg4_HW_Ver_Byte14_54 "SBMU硬件版本号Byte14对应的ASCII码";
CM_ SG_ 2416307830 S2P_Cfg4_HW_Ver_Byte15_54 "SBMU硬件版本号Byte15对应的ASCII码";
CM_ SG_ 2416307830 S2P_Cfg4_HW_Ver_Byte16_54 "SBMU硬件版本号最高字节Byte16对应的ASCII码";
CM_ SG_ 2416307831 S2P_Cfg4_HW_Ver_Byte9_55 "SBMU硬件版本号Byte9对应的ASCII码";
CM_ SG_ 2416307831 S2P_Cfg4_HW_Ver_Byte10_55 "SBMU硬件版本号Byte10对应的ASCII码";
CM_ SG_ 2416307831 S2P_Cfg4_HW_Ver_Byte11_55 "SBMU硬件版本号Byte11对应的ASCII码";
CM_ SG_ 2416307831 S2P_Cfg4_HW_Ver_Byte12_55 "SBMU硬件版本号Byte12对应的ASCII码";
CM_ SG_ 2416307831 S2P_Cfg4_HW_Ver_Byte13_55 "SBMU硬件版本号Byte13对应的ASCII码";
CM_ SG_ 2416307831 S2P_Cfg4_HW_Ver_Byte14_55 "SBMU硬件版本号Byte14对应的ASCII码";
CM_ SG_ 2416307831 S2P_Cfg4_HW_Ver_Byte15_55 "SBMU硬件版本号Byte15对应的ASCII码";
CM_ SG_ 2416307831 S2P_Cfg4_HW_Ver_Byte16_55 "SBMU硬件版本号最高字节Byte16对应的ASCII码";
CM_ SG_ 2416307832 S2P_Cfg4_HW_Ver_Byte9_56 "SBMU硬件版本号Byte9对应的ASCII码";
CM_ SG_ 2416307832 S2P_Cfg4_HW_Ver_Byte10_56 "SBMU硬件版本号Byte10对应的ASCII码";
CM_ SG_ 2416307832 S2P_Cfg4_HW_Ver_Byte11_56 "SBMU硬件版本号Byte11对应的ASCII码";
CM_ SG_ 2416307832 S2P_Cfg4_HW_Ver_Byte12_56 "SBMU硬件版本号Byte12对应的ASCII码";
CM_ SG_ 2416307832 S2P_Cfg4_HW_Ver_Byte13_56 "SBMU硬件版本号Byte13对应的ASCII码";
CM_ SG_ 2416307832 S2P_Cfg4_HW_Ver_Byte14_56 "SBMU硬件版本号Byte14对应的ASCII码";
CM_ SG_ 2416307832 S2P_Cfg4_HW_Ver_Byte15_56 "SBMU硬件版本号Byte15对应的ASCII码";
CM_ SG_ 2416307832 S2P_Cfg4_HW_Ver_Byte16_56 "SBMU硬件版本号最高字节Byte16对应的ASCII码";
CM_ SG_ 2416307833 S2P_Cfg4_HW_Ver_Byte9_57 "SBMU硬件版本号Byte9对应的ASCII码";
CM_ SG_ 2416307833 S2P_Cfg4_HW_Ver_Byte10_57 "SBMU硬件版本号Byte10对应的ASCII码";
CM_ SG_ 2416307833 S2P_Cfg4_HW_Ver_Byte11_57 "SBMU硬件版本号Byte11对应的ASCII码";
CM_ SG_ 2416307833 S2P_Cfg4_HW_Ver_Byte12_57 "SBMU硬件版本号Byte12对应的ASCII码";
CM_ SG_ 2416307833 S2P_Cfg4_HW_Ver_Byte13_57 "SBMU硬件版本号Byte13对应的ASCII码";
CM_ SG_ 2416307833 S2P_Cfg4_HW_Ver_Byte14_57 "SBMU硬件版本号Byte14对应的ASCII码";
CM_ SG_ 2416307833 S2P_Cfg4_HW_Ver_Byte15_57 "SBMU硬件版本号Byte15对应的ASCII码";
CM_ SG_ 2416307833 S2P_Cfg4_HW_Ver_Byte16_57 "SBMU硬件版本号最高字节Byte16对应的ASCII码";
CM_ SG_ 2416307834 S2P_Cfg4_HW_Ver_Byte9_58 "SBMU硬件版本号Byte9对应的ASCII码";
CM_ SG_ 2416307834 S2P_Cfg4_HW_Ver_Byte10_58 "SBMU硬件版本号Byte10对应的ASCII码";
CM_ SG_ 2416307834 S2P_Cfg4_HW_Ver_Byte11_58 "SBMU硬件版本号Byte11对应的ASCII码";
CM_ SG_ 2416307834 S2P_Cfg4_HW_Ver_Byte12_58 "SBMU硬件版本号Byte12对应的ASCII码";
CM_ SG_ 2416307834 S2P_Cfg4_HW_Ver_Byte13_58 "SBMU硬件版本号Byte13对应的ASCII码";
CM_ SG_ 2416307834 S2P_Cfg4_HW_Ver_Byte14_58 "SBMU硬件版本号Byte14对应的ASCII码";
CM_ SG_ 2416307834 S2P_Cfg4_HW_Ver_Byte15_58 "SBMU硬件版本号Byte15对应的ASCII码";
CM_ SG_ 2416307834 S2P_Cfg4_HW_Ver_Byte16_58 "SBMU硬件版本号最高字节Byte16对应的ASCII码";
CM_ SG_ 2416307835 S2P_Cfg4_HW_Ver_Byte9_59 "SBMU硬件版本号Byte9对应的ASCII码";
CM_ SG_ 2416307835 S2P_Cfg4_HW_Ver_Byte10_59 "SBMU硬件版本号Byte10对应的ASCII码";
CM_ SG_ 2416307835 S2P_Cfg4_HW_Ver_Byte11_59 "SBMU硬件版本号Byte11对应的ASCII码";
CM_ SG_ 2416307835 S2P_Cfg4_HW_Ver_Byte12_59 "SBMU硬件版本号Byte12对应的ASCII码";
CM_ SG_ 2416307835 S2P_Cfg4_HW_Ver_Byte13_59 "SBMU硬件版本号Byte13对应的ASCII码";
CM_ SG_ 2416307835 S2P_Cfg4_HW_Ver_Byte14_59 "SBMU硬件版本号Byte14对应的ASCII码";
CM_ SG_ 2416307835 S2P_Cfg4_HW_Ver_Byte15_59 "SBMU硬件版本号Byte15对应的ASCII码";
CM_ SG_ 2416307835 S2P_Cfg4_HW_Ver_Byte16_59 "SBMU硬件版本号最高字节Byte16对应的ASCII码";
CM_ SG_ 2416307836 S2P_Cfg4_HW_Ver_Byte9_60 "SBMU硬件版本号Byte9对应的ASCII码";
CM_ SG_ 2416307836 S2P_Cfg4_HW_Ver_Byte10_60 "SBMU硬件版本号Byte10对应的ASCII码";
CM_ SG_ 2416307836 S2P_Cfg4_HW_Ver_Byte11_60 "SBMU硬件版本号Byte11对应的ASCII码";
CM_ SG_ 2416307836 S2P_Cfg4_HW_Ver_Byte12_60 "SBMU硬件版本号Byte12对应的ASCII码";
CM_ SG_ 2416307836 S2P_Cfg4_HW_Ver_Byte13_60 "SBMU硬件版本号Byte13对应的ASCII码";
CM_ SG_ 2416307836 S2P_Cfg4_HW_Ver_Byte14_60 "SBMU硬件版本号Byte14对应的ASCII码";
CM_ SG_ 2416307836 S2P_Cfg4_HW_Ver_Byte15_60 "SBMU硬件版本号Byte15对应的ASCII码";
CM_ SG_ 2416307836 S2P_Cfg4_HW_Ver_Byte16_60 "SBMU硬件版本号最高字节Byte16对应的ASCII码";
CM_ SG_ 2416307837 S2P_Cfg4_HW_Ver_Byte9_61 "SBMU硬件版本号Byte9对应的ASCII码";
CM_ SG_ 2416307837 S2P_Cfg4_HW_Ver_Byte10_61 "SBMU硬件版本号Byte10对应的ASCII码";
CM_ SG_ 2416307837 S2P_Cfg4_HW_Ver_Byte11_61 "SBMU硬件版本号Byte11对应的ASCII码";
CM_ SG_ 2416307837 S2P_Cfg4_HW_Ver_Byte12_61 "SBMU硬件版本号Byte12对应的ASCII码";
CM_ SG_ 2416307837 S2P_Cfg4_HW_Ver_Byte13_61 "SBMU硬件版本号Byte13对应的ASCII码";
CM_ SG_ 2416307837 S2P_Cfg4_HW_Ver_Byte14_61 "SBMU硬件版本号Byte14对应的ASCII码";
CM_ SG_ 2416307837 S2P_Cfg4_HW_Ver_Byte15_61 "SBMU硬件版本号Byte15对应的ASCII码";
CM_ SG_ 2416307837 S2P_Cfg4_HW_Ver_Byte16_61 "SBMU硬件版本号最高字节Byte16对应的ASCII码";
CM_ SG_ 2416307838 S2P_Cfg4_HW_Ver_Byte9_62 "SBMU硬件版本号Byte9对应的ASCII码";
CM_ SG_ 2416307838 S2P_Cfg4_HW_Ver_Byte10_62 "SBMU硬件版本号Byte10对应的ASCII码";
CM_ SG_ 2416307838 S2P_Cfg4_HW_Ver_Byte11_62 "SBMU硬件版本号Byte11对应的ASCII码";
CM_ SG_ 2416307838 S2P_Cfg4_HW_Ver_Byte12_62 "SBMU硬件版本号Byte12对应的ASCII码";
CM_ SG_ 2416307838 S2P_Cfg4_HW_Ver_Byte13_62 "SBMU硬件版本号Byte13对应的ASCII码";
CM_ SG_ 2416307838 S2P_Cfg4_HW_Ver_Byte14_62 "SBMU硬件版本号Byte14对应的ASCII码";
CM_ SG_ 2416307838 S2P_Cfg4_HW_Ver_Byte15_62 "SBMU硬件版本号Byte15对应的ASCII码";
CM_ SG_ 2416307838 S2P_Cfg4_HW_Ver_Byte16_62 "SBMU硬件版本号最高字节Byte16对应的ASCII码";
CM_ SG_ 2416307839 S2P_Cfg4_HW_Ver_Byte9_63 "SBMU硬件版本号Byte9对应的ASCII码";
CM_ SG_ 2416307839 S2P_Cfg4_HW_Ver_Byte10_63 "SBMU硬件版本号Byte10对应的ASCII码";
CM_ SG_ 2416307839 S2P_Cfg4_HW_Ver_Byte11_63 "SBMU硬件版本号Byte11对应的ASCII码";
CM_ SG_ 2416307839 S2P_Cfg4_HW_Ver_Byte12_63 "SBMU硬件版本号Byte12对应的ASCII码";
CM_ SG_ 2416307839 S2P_Cfg4_HW_Ver_Byte13_63 "SBMU硬件版本号Byte13对应的ASCII码";
CM_ SG_ 2416307839 S2P_Cfg4_HW_Ver_Byte14_63 "SBMU硬件版本号Byte14对应的ASCII码";
CM_ SG_ 2416307839 S2P_Cfg4_HW_Ver_Byte15_63 "SBMU硬件版本号Byte15对应的ASCII码";
CM_ SG_ 2416307839 S2P_Cfg4_HW_Ver_Byte16_63 "SBMU硬件版本号最高字节Byte16对应的ASCII码";
CM_ SG_ 2416373313 S2P_Cfg5_SBMU_Add_01 "SBMU的地址";
CM_ SG_ 2416373313 S2P_Cfg5_ModuleParal_Num_01 "当前SBMU模组并联数量？确认内容 wgw:PAL_CSC_COUNT固定为1";
CM_ SG_ 2416373313 S2P_Cfg5_CellSeries_Num_01 "电柜串联电芯数   CELL_NO *NUM_OF_CSC";
CM_ SG_ 2416373313 S2P_Cfg5_Temps_Num_01 "当前SBMU管理的环境温度采样点数目";
CM_ SG_ 2416373313 S2P_Cfg5_CSCs_Num_01 "当前SBMU管理的CSC数目";
CM_ SG_ 2416373313 S2P_Cfg5_Utank_Norminal_01 "分柜标称电压";
CM_ SG_ 2416373313 S2P_Cfg5_CSCType_01 "CSC类型";
CM_ SG_ 2416373314 S2P_Cfg5_SBMU_Add_02 "SBMU的地址";
CM_ SG_ 2416373314 S2P_Cfg5_ModuleParal_Num_02 "当前SBMU模组并联数量？确认内容 wgw:PAL_CSC_COUNT固定为1";
CM_ SG_ 2416373314 S2P_Cfg5_CellSeries_Num_02 "电柜串联电芯数   CELL_NO *NUM_OF_CSC";
CM_ SG_ 2416373314 S2P_Cfg5_Temps_Num_02 "当前SBMU管理的环境温度采样点数目";
CM_ SG_ 2416373314 S2P_Cfg5_CSCs_Num_02 "当前SBMU管理的CSC数目";
CM_ SG_ 2416373314 S2P_Cfg5_Utank_Norminal_02 "分柜标称电压";
CM_ SG_ 2416373314 S2P_Cfg5_CSCType_02 "CSC类型";
CM_ SG_ 2416373315 S2P_Cfg5_SBMU_Add_03 "SBMU的地址";
CM_ SG_ 2416373315 S2P_Cfg5_ModuleParal_Num_03 "当前SBMU模组并联数量？确认内容 wgw:PAL_CSC_COUNT固定为1";
CM_ SG_ 2416373315 S2P_Cfg5_CellSeries_Num_03 "电柜串联电芯数   CELL_NO *NUM_OF_CSC";
CM_ SG_ 2416373315 S2P_Cfg5_Temps_Num_03 "当前SBMU管理的环境温度采样点数目";
CM_ SG_ 2416373315 S2P_Cfg5_CSCs_Num_03 "当前SBMU管理的CSC数目";
CM_ SG_ 2416373315 S2P_Cfg5_Utank_Norminal_03 "分柜标称电压";
CM_ SG_ 2416373315 S2P_Cfg5_CSCType_03 "CSC类型";
CM_ SG_ 2416373316 S2P_Cfg5_SBMU_Add_04 "SBMU的地址";
CM_ SG_ 2416373316 S2P_Cfg5_ModuleParal_Num_04 "当前SBMU模组并联数量？确认内容 wgw:PAL_CSC_COUNT固定为1";
CM_ SG_ 2416373316 S2P_Cfg5_CellSeries_Num_04 "电柜串联电芯数   CELL_NO *NUM_OF_CSC";
CM_ SG_ 2416373316 S2P_Cfg5_Temps_Num_04 "当前SBMU管理的环境温度采样点数目";
CM_ SG_ 2416373316 S2P_Cfg5_CSCs_Num_04 "当前SBMU管理的CSC数目";
CM_ SG_ 2416373316 S2P_Cfg5_Utank_Norminal_04 "分柜标称电压";
CM_ SG_ 2416373316 S2P_Cfg5_CSCType_04 "CSC类型";
CM_ SG_ 2416373317 S2P_Cfg5_SBMU_Add_05 "SBMU的地址";
CM_ SG_ 2416373317 S2P_Cfg5_ModuleParal_Num_05 "当前SBMU模组并联数量？确认内容 wgw:PAL_CSC_COUNT固定为1";
CM_ SG_ 2416373317 S2P_Cfg5_CellSeries_Num_05 "电柜串联电芯数   CELL_NO *NUM_OF_CSC";
CM_ SG_ 2416373317 S2P_Cfg5_Temps_Num_05 "当前SBMU管理的环境温度采样点数目";
CM_ SG_ 2416373317 S2P_Cfg5_CSCs_Num_05 "当前SBMU管理的CSC数目";
CM_ SG_ 2416373317 S2P_Cfg5_Utank_Norminal_05 "分柜标称电压";
CM_ SG_ 2416373317 S2P_Cfg5_CSCType_05 "CSC类型";
CM_ SG_ 2416373318 S2P_Cfg5_SBMU_Add_06 "SBMU的地址";
CM_ SG_ 2416373318 S2P_Cfg5_ModuleParal_Num_06 "当前SBMU模组并联数量？确认内容 wgw:PAL_CSC_COUNT固定为1";
CM_ SG_ 2416373318 S2P_Cfg5_CellSeries_Num_06 "电柜串联电芯数   CELL_NO *NUM_OF_CSC";
CM_ SG_ 2416373318 S2P_Cfg5_Temps_Num_06 "当前SBMU管理的环境温度采样点数目";
CM_ SG_ 2416373318 S2P_Cfg5_CSCs_Num_06 "当前SBMU管理的CSC数目";
CM_ SG_ 2416373318 S2P_Cfg5_Utank_Norminal_06 "分柜标称电压";
CM_ SG_ 2416373318 S2P_Cfg5_CSCType_06 "CSC类型";
CM_ SG_ 2416373319 S2P_Cfg5_SBMU_Add_07 "SBMU的地址";
CM_ SG_ 2416373319 S2P_Cfg5_ModuleParal_Num_07 "当前SBMU模组并联数量？确认内容 wgw:PAL_CSC_COUNT固定为1";
CM_ SG_ 2416373319 S2P_Cfg5_CellSeries_Num_07 "电柜串联电芯数   CELL_NO *NUM_OF_CSC";
CM_ SG_ 2416373319 S2P_Cfg5_Temps_Num_07 "当前SBMU管理的环境温度采样点数目";
CM_ SG_ 2416373319 S2P_Cfg5_CSCs_Num_07 "当前SBMU管理的CSC数目";
CM_ SG_ 2416373319 S2P_Cfg5_Utank_Norminal_07 "分柜标称电压";
CM_ SG_ 2416373319 S2P_Cfg5_CSCType_07 "CSC类型";
CM_ SG_ 2416373320 S2P_Cfg5_SBMU_Add_08 "SBMU的地址";
CM_ SG_ 2416373320 S2P_Cfg5_ModuleParal_Num_08 "当前SBMU模组并联数量？确认内容 wgw:PAL_CSC_COUNT固定为1";
CM_ SG_ 2416373320 S2P_Cfg5_CellSeries_Num_08 "电柜串联电芯数   CELL_NO *NUM_OF_CSC";
CM_ SG_ 2416373320 S2P_Cfg5_Temps_Num_08 "当前SBMU管理的环境温度采样点数目";
CM_ SG_ 2416373320 S2P_Cfg5_CSCs_Num_08 "当前SBMU管理的CSC数目";
CM_ SG_ 2416373320 S2P_Cfg5_Utank_Norminal_08 "分柜标称电压";
CM_ SG_ 2416373320 S2P_Cfg5_CSCType_08 "CSC类型";
CM_ SG_ 2416373321 S2P_Cfg5_SBMU_Add_09 "SBMU的地址";
CM_ SG_ 2416373321 S2P_Cfg5_ModuleParal_Num_09 "当前SBMU模组并联数量？确认内容 wgw:PAL_CSC_COUNT固定为1";
CM_ SG_ 2416373321 S2P_Cfg5_CellSeries_Num_09 "电柜串联电芯数   CELL_NO *NUM_OF_CSC";
CM_ SG_ 2416373321 S2P_Cfg5_Temps_Num_09 "当前SBMU管理的环境温度采样点数目";
CM_ SG_ 2416373321 S2P_Cfg5_CSCs_Num_09 "当前SBMU管理的CSC数目";
CM_ SG_ 2416373321 S2P_Cfg5_Utank_Norminal_09 "分柜标称电压";
CM_ SG_ 2416373321 S2P_Cfg5_CSCType_09 "CSC类型";
CM_ SG_ 2416373322 S2P_Cfg5_SBMU_Add_10 "SBMU的地址";
CM_ SG_ 2416373322 S2P_Cfg5_ModuleParal_Num_10 "当前SBMU模组并联数量？确认内容 wgw:PAL_CSC_COUNT固定为1";
CM_ SG_ 2416373322 S2P_Cfg5_CellSeries_Num_10 "电柜串联电芯数   CELL_NO *NUM_OF_CSC";
CM_ SG_ 2416373322 S2P_Cfg5_Temps_Num_10 "当前SBMU管理的环境温度采样点数目";
CM_ SG_ 2416373322 S2P_Cfg5_CSCs_Num_10 "当前SBMU管理的CSC数目";
CM_ SG_ 2416373322 S2P_Cfg5_Utank_Norminal_10 "分柜标称电压";
CM_ SG_ 2416373322 S2P_Cfg5_CSCType_10 "CSC类型";
CM_ SG_ 2416373323 S2P_Cfg5_SBMU_Add_11 "SBMU的地址";
CM_ SG_ 2416373323 S2P_Cfg5_ModuleParal_Num_11 "当前SBMU模组并联数量？确认内容 wgw:PAL_CSC_COUNT固定为1";
CM_ SG_ 2416373323 S2P_Cfg5_CellSeries_Num_11 "电柜串联电芯数   CELL_NO *NUM_OF_CSC";
CM_ SG_ 2416373323 S2P_Cfg5_Temps_Num_11 "当前SBMU管理的环境温度采样点数目";
CM_ SG_ 2416373323 S2P_Cfg5_CSCs_Num_11 "当前SBMU管理的CSC数目";
CM_ SG_ 2416373323 S2P_Cfg5_Utank_Norminal_11 "分柜标称电压";
CM_ SG_ 2416373323 S2P_Cfg5_CSCType_11 "CSC类型";
CM_ SG_ 2416373324 S2P_Cfg5_SBMU_Add_12 "SBMU的地址";
CM_ SG_ 2416373324 S2P_Cfg5_ModuleParal_Num_12 "当前SBMU模组并联数量？确认内容 wgw:PAL_CSC_COUNT固定为1";
CM_ SG_ 2416373324 S2P_Cfg5_CellSeries_Num_12 "电柜串联电芯数   CELL_NO *NUM_OF_CSC";
CM_ SG_ 2416373324 S2P_Cfg5_Temps_Num_12 "当前SBMU管理的环境温度采样点数目";
CM_ SG_ 2416373324 S2P_Cfg5_CSCs_Num_12 "当前SBMU管理的CSC数目";
CM_ SG_ 2416373324 S2P_Cfg5_Utank_Norminal_12 "分柜标称电压";
CM_ SG_ 2416373324 S2P_Cfg5_CSCType_12 "CSC类型";
CM_ SG_ 2416373325 S2P_Cfg5_SBMU_Add_13 "SBMU的地址";
CM_ SG_ 2416373325 S2P_Cfg5_ModuleParal_Num_13 "当前SBMU模组并联数量？确认内容 wgw:PAL_CSC_COUNT固定为1";
CM_ SG_ 2416373325 S2P_Cfg5_CellSeries_Num_13 "电柜串联电芯数   CELL_NO *NUM_OF_CSC";
CM_ SG_ 2416373325 S2P_Cfg5_Temps_Num_13 "当前SBMU管理的环境温度采样点数目";
CM_ SG_ 2416373325 S2P_Cfg5_CSCs_Num_13 "当前SBMU管理的CSC数目";
CM_ SG_ 2416373325 S2P_Cfg5_Utank_Norminal_13 "分柜标称电压";
CM_ SG_ 2416373325 S2P_Cfg5_CSCType_13 "CSC类型";
CM_ SG_ 2416373326 S2P_Cfg5_SBMU_Add_14 "SBMU的地址";
CM_ SG_ 2416373326 S2P_Cfg5_ModuleParal_Num_14 "当前SBMU模组并联数量？确认内容 wgw:PAL_CSC_COUNT固定为1";
CM_ SG_ 2416373326 S2P_Cfg5_CellSeries_Num_14 "电柜串联电芯数   CELL_NO *NUM_OF_CSC";
CM_ SG_ 2416373326 S2P_Cfg5_Temps_Num_14 "当前SBMU管理的环境温度采样点数目";
CM_ SG_ 2416373326 S2P_Cfg5_CSCs_Num_14 "当前SBMU管理的CSC数目";
CM_ SG_ 2416373326 S2P_Cfg5_Utank_Norminal_14 "分柜标称电压";
CM_ SG_ 2416373326 S2P_Cfg5_CSCType_14 "CSC类型";
CM_ SG_ 2416373327 S2P_Cfg5_SBMU_Add_15 "SBMU的地址";
CM_ SG_ 2416373327 S2P_Cfg5_ModuleParal_Num_15 "当前SBMU模组并联数量？确认内容 wgw:PAL_CSC_COUNT固定为1";
CM_ SG_ 2416373327 S2P_Cfg5_CellSeries_Num_15 "电柜串联电芯数   CELL_NO *NUM_OF_CSC";
CM_ SG_ 2416373327 S2P_Cfg5_Temps_Num_15 "当前SBMU管理的环境温度采样点数目";
CM_ SG_ 2416373327 S2P_Cfg5_CSCs_Num_15 "当前SBMU管理的CSC数目";
CM_ SG_ 2416373327 S2P_Cfg5_Utank_Norminal_15 "分柜标称电压";
CM_ SG_ 2416373327 S2P_Cfg5_CSCType_15 "CSC类型";
CM_ SG_ 2416373328 S2P_Cfg5_SBMU_Add_16 "SBMU的地址";
CM_ SG_ 2416373328 S2P_Cfg5_ModuleParal_Num_16 "当前SBMU模组并联数量？确认内容 wgw:PAL_CSC_COUNT固定为1";
CM_ SG_ 2416373328 S2P_Cfg5_CellSeries_Num_16 "电柜串联电芯数   CELL_NO *NUM_OF_CSC";
CM_ SG_ 2416373328 S2P_Cfg5_Temps_Num_16 "当前SBMU管理的环境温度采样点数目";
CM_ SG_ 2416373328 S2P_Cfg5_CSCs_Num_16 "当前SBMU管理的CSC数目";
CM_ SG_ 2416373328 S2P_Cfg5_Utank_Norminal_16 "分柜标称电压";
CM_ SG_ 2416373328 S2P_Cfg5_CSCType_16 "CSC类型";
CM_ SG_ 2416373329 S2P_Cfg5_SBMU_Add_17 "SBMU的地址";
CM_ SG_ 2416373329 S2P_Cfg5_ModuleParal_Num_17 "当前SBMU模组并联数量？确认内容 wgw:PAL_CSC_COUNT固定为1";
CM_ SG_ 2416373329 S2P_Cfg5_CellSeries_Num_17 "电柜串联电芯数   CELL_NO *NUM_OF_CSC";
CM_ SG_ 2416373329 S2P_Cfg5_Temps_Num_17 "当前SBMU管理的环境温度采样点数目";
CM_ SG_ 2416373329 S2P_Cfg5_CSCs_Num_17 "当前SBMU管理的CSC数目";
CM_ SG_ 2416373329 S2P_Cfg5_Utank_Norminal_17 "分柜标称电压";
CM_ SG_ 2416373329 S2P_Cfg5_CSCType_17 "CSC类型";
CM_ SG_ 2416373330 S2P_Cfg5_SBMU_Add_18 "SBMU的地址";
CM_ SG_ 2416373330 S2P_Cfg5_ModuleParal_Num_18 "当前SBMU模组并联数量？确认内容 wgw:PAL_CSC_COUNT固定为1";
CM_ SG_ 2416373330 S2P_Cfg5_CellSeries_Num_18 "电柜串联电芯数   CELL_NO *NUM_OF_CSC";
CM_ SG_ 2416373330 S2P_Cfg5_Temps_Num_18 "当前SBMU管理的环境温度采样点数目";
CM_ SG_ 2416373330 S2P_Cfg5_CSCs_Num_18 "当前SBMU管理的CSC数目";
CM_ SG_ 2416373330 S2P_Cfg5_Utank_Norminal_18 "分柜标称电压";
CM_ SG_ 2416373330 S2P_Cfg5_CSCType_18 "CSC类型";
CM_ SG_ 2416373331 S2P_Cfg5_SBMU_Add_19 "SBMU的地址";
CM_ SG_ 2416373331 S2P_Cfg5_ModuleParal_Num_19 "当前SBMU模组并联数量？确认内容 wgw:PAL_CSC_COUNT固定为1";
CM_ SG_ 2416373331 S2P_Cfg5_CellSeries_Num_19 "电柜串联电芯数   CELL_NO *NUM_OF_CSC";
CM_ SG_ 2416373331 S2P_Cfg5_Temps_Num_19 "当前SBMU管理的环境温度采样点数目";
CM_ SG_ 2416373331 S2P_Cfg5_CSCs_Num_19 "当前SBMU管理的CSC数目";
CM_ SG_ 2416373331 S2P_Cfg5_Utank_Norminal_19 "分柜标称电压";
CM_ SG_ 2416373331 S2P_Cfg5_CSCType_19 "CSC类型";
CM_ SG_ 2416373332 S2P_Cfg5_SBMU_Add_20 "SBMU的地址";
CM_ SG_ 2416373332 S2P_Cfg5_ModuleParal_Num_20 "当前SBMU模组并联数量？确认内容 wgw:PAL_CSC_COUNT固定为1";
CM_ SG_ 2416373332 S2P_Cfg5_CellSeries_Num_20 "电柜串联电芯数   CELL_NO *NUM_OF_CSC";
CM_ SG_ 2416373332 S2P_Cfg5_Temps_Num_20 "当前SBMU管理的环境温度采样点数目";
CM_ SG_ 2416373332 S2P_Cfg5_CSCs_Num_20 "当前SBMU管理的CSC数目";
CM_ SG_ 2416373332 S2P_Cfg5_Utank_Norminal_20 "分柜标称电压";
CM_ SG_ 2416373332 S2P_Cfg5_CSCType_20 "CSC类型";
CM_ SG_ 2416373333 S2P_Cfg5_SBMU_Add_21 "SBMU的地址";
CM_ SG_ 2416373333 S2P_Cfg5_ModuleParal_Num_21 "当前SBMU模组并联数量？确认内容 wgw:PAL_CSC_COUNT固定为1";
CM_ SG_ 2416373333 S2P_Cfg5_CellSeries_Num_21 "电柜串联电芯数   CELL_NO *NUM_OF_CSC";
CM_ SG_ 2416373333 S2P_Cfg5_Temps_Num_21 "当前SBMU管理的环境温度采样点数目";
CM_ SG_ 2416373333 S2P_Cfg5_CSCs_Num_21 "当前SBMU管理的CSC数目";
CM_ SG_ 2416373333 S2P_Cfg5_Utank_Norminal_21 "分柜标称电压";
CM_ SG_ 2416373333 S2P_Cfg5_CSCType_21 "CSC类型";
CM_ SG_ 2416373334 S2P_Cfg5_SBMU_Add_22 "SBMU的地址";
CM_ SG_ 2416373334 S2P_Cfg5_ModuleParal_Num_22 "当前SBMU模组并联数量？确认内容 wgw:PAL_CSC_COUNT固定为1";
CM_ SG_ 2416373334 S2P_Cfg5_CellSeries_Num_22 "电柜串联电芯数   CELL_NO *NUM_OF_CSC";
CM_ SG_ 2416373334 S2P_Cfg5_Temps_Num_22 "当前SBMU管理的环境温度采样点数目";
CM_ SG_ 2416373334 S2P_Cfg5_CSCs_Num_22 "当前SBMU管理的CSC数目";
CM_ SG_ 2416373334 S2P_Cfg5_Utank_Norminal_22 "分柜标称电压";
CM_ SG_ 2416373334 S2P_Cfg5_CSCType_22 "CSC类型";
CM_ SG_ 2416373335 S2P_Cfg5_SBMU_Add_23 "SBMU的地址";
CM_ SG_ 2416373335 S2P_Cfg5_ModuleParal_Num_23 "当前SBMU模组并联数量？确认内容 wgw:PAL_CSC_COUNT固定为1";
CM_ SG_ 2416373335 S2P_Cfg5_CellSeries_Num_23 "电柜串联电芯数   CELL_NO *NUM_OF_CSC";
CM_ SG_ 2416373335 S2P_Cfg5_Temps_Num_23 "当前SBMU管理的环境温度采样点数目";
CM_ SG_ 2416373335 S2P_Cfg5_CSCs_Num_23 "当前SBMU管理的CSC数目";
CM_ SG_ 2416373335 S2P_Cfg5_Utank_Norminal_23 "分柜标称电压";
CM_ SG_ 2416373335 S2P_Cfg5_CSCType_23 "CSC类型";
CM_ SG_ 2416373336 S2P_Cfg5_SBMU_Add_24 "SBMU的地址";
CM_ SG_ 2416373336 S2P_Cfg5_ModuleParal_Num_24 "当前SBMU模组并联数量？确认内容 wgw:PAL_CSC_COUNT固定为1";
CM_ SG_ 2416373336 S2P_Cfg5_CellSeries_Num_24 "电柜串联电芯数   CELL_NO *NUM_OF_CSC";
CM_ SG_ 2416373336 S2P_Cfg5_Temps_Num_24 "当前SBMU管理的环境温度采样点数目";
CM_ SG_ 2416373336 S2P_Cfg5_CSCs_Num_24 "当前SBMU管理的CSC数目";
CM_ SG_ 2416373336 S2P_Cfg5_Utank_Norminal_24 "分柜标称电压";
CM_ SG_ 2416373336 S2P_Cfg5_CSCType_24 "CSC类型";
VAL_ 2416373313 S2P_Cfg5_CSCType_01 0 "PBV1.1_52S_16 CSC" 1 "PBV1.1_52S_52_CSC" 2 "PBV1.1_104S_60 CSC" ;
VAL_ 2416373314 S2P_Cfg5_CSCType_02 0 "PBV1.1_52S_16 CSC" 1 "PBV1.1_52S_52_CSC" 2 "PBV1.1_104S_60 CSC" ;
VAL_ 2416373315 S2P_Cfg5_CSCType_03 0 "PBV1.1_52S_16 CSC" 1 "PBV1.1_52S_52_CSC" 2 "PBV1.1_104S_60 CSC" ;
VAL_ 2416373316 S2P_Cfg5_CSCType_04 0 "PBV1.1_52S_16 CSC" 1 "PBV1.1_52S_52_CSC" 2 "PBV1.1_104S_60 CSC" ;
VAL_ 2416373317 S2P_Cfg5_CSCType_05 0 "PBV1.1_52S_16 CSC" 1 "PBV1.1_52S_52_CSC" 2 "PBV1.1_104S_60 CSC" ;
VAL_ 2416373318 S2P_Cfg5_CSCType_06 0 "PBV1.1_52S_16 CSC" 1 "PBV1.1_52S_52_CSC" 2 "PBV1.1_104S_60 CSC" ;
VAL_ 2416373319 S2P_Cfg5_CSCType_07 0 "PBV1.1_52S_16 CSC" 1 "PBV1.1_52S_52_CSC" 2 "PBV1.1_104S_60 CSC" ;
VAL_ 2416373320 S2P_Cfg5_CSCType_08 0 "PBV1.1_52S_16 CSC" 1 "PBV1.1_52S_52_CSC" 2 "PBV1.1_104S_60 CSC" ;
VAL_ 2416373321 S2P_Cfg5_CSCType_09 0 "PBV1.1_52S_16 CSC" 1 "PBV1.1_52S_52_CSC" 2 "PBV1.1_104S_60 CSC" ;
VAL_ 2416373322 S2P_Cfg5_CSCType_10 0 "PBV1.1_52S_16 CSC" 1 "PBV1.1_52S_52_CSC" 2 "PBV1.1_104S_60 CSC" ;
VAL_ 2416373323 S2P_Cfg5_CSCType_11 0 "PBV1.1_52S_16 CSC" 1 "PBV1.1_52S_52_CSC" 2 "PBV1.1_104S_60 CSC" ;
VAL_ 2416373324 S2P_Cfg5_CSCType_12 0 "PBV1.1_52S_16 CSC" 1 "PBV1.1_52S_52_CSC" 2 "PBV1.1_104S_60 CSC" ;
VAL_ 2416373325 S2P_Cfg5_CSCType_13 0 "PBV1.1_52S_16 CSC" 1 "PBV1.1_52S_52_CSC" 2 "PBV1.1_104S_60 CSC" ;
VAL_ 2416373326 S2P_Cfg5_CSCType_14 0 "PBV1.1_52S_16 CSC" 1 "PBV1.1_52S_52_CSC" 2 "PBV1.1_104S_60 CSC" ;
VAL_ 2416373327 S2P_Cfg5_CSCType_15 0 "PBV1.1_52S_16 CSC" 1 "PBV1.1_52S_52_CSC" 2 "PBV1.1_104S_60 CSC" ;
VAL_ 2416373328 S2P_Cfg5_CSCType_16 0 "PBV1.1_52S_16 CSC" 1 "PBV1.1_52S_52_CSC" 2 "PBV1.1_104S_60 CSC" ;
VAL_ 2416373329 S2P_Cfg5_CSCType_17 0 "PBV1.1_52S_16 CSC" 1 "PBV1.1_52S_52_CSC" 2 "PBV1.1_104S_60 CSC" ;
VAL_ 2416373330 S2P_Cfg5_CSCType_18 0 "PBV1.1_52S_16 CSC" 1 "PBV1.1_52S_52_CSC" 2 "PBV1.1_104S_60 CSC" ;
VAL_ 2416373331 S2P_Cfg5_CSCType_19 0 "PBV1.1_52S_16 CSC" 1 "PBV1.1_52S_52_CSC" 2 "PBV1.1_104S_60 CSC" ;
VAL_ 2416373332 S2P_Cfg5_CSCType_20 0 "PBV1.1_52S_16 CSC" 1 "PBV1.1_52S_52_CSC" 2 "PBV1.1_104S_60 CSC" ;
VAL_ 2416373333 S2P_Cfg5_CSCType_21 0 "PBV1.1_52S_16 CSC" 1 "PBV1.1_52S_52_CSC" 2 "PBV1.1_104S_60 CSC" ;
VAL_ 2416373334 S2P_Cfg5_CSCType_22 0 "PBV1.1_52S_16 CSC" 1 "PBV1.1_52S_52_CSC" 2 "PBV1.1_104S_60 CSC" ;
VAL_ 2416373335 S2P_Cfg5_CSCType_23 0 "PBV1.1_52S_16 CSC" 1 "PBV1.1_52S_52_CSC" 2 "PBV1.1_104S_60 CSC" ;
VAL_ 2416373336 S2P_Cfg5_CSCType_24 0 "PBV1.1_52S_16 CSC" 1 "PBV1.1_52S_52_CSC" 2 "PBV1.1_104S_60 CSC" ;
VERSION ""

NS_ :

BS_:

BU_: MBMU PC SBMU IMM ETH DCDC LEMS

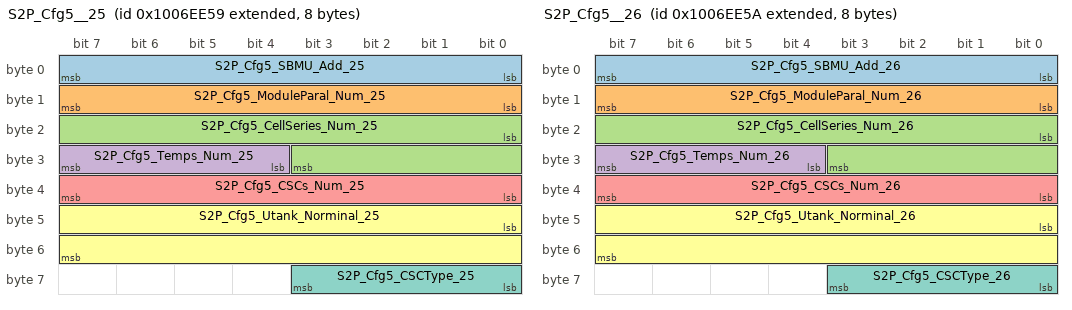
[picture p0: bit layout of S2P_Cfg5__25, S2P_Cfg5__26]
BO_ 2416373337 S2P_Cfg5__25: 8 SBMU
 SG_ S2P_Cfg5_SBMU_Add_25 : 0|8@1+ (1,0) [0|255] ""  PC
 SG_ S2P_Cfg5_ModuleParal_Num_25 : 8|8@1+ (1,0) [0|255] ""  PC
 SG_ S2P_Cfg5_CellSeries_Num_25 : 16|12@1+ (1,0) [0|4095] ""  PC
 SG_ S2P_Cfg5_Temps_Num_25 : 28|4@1+ (1,0) [0|15] ""  PC
 SG_ S2P_Cfg5_CSCs_Num_25 : 32|8@1+ (1,0) [0|255] ""  PC
 SG_ S2P_Cfg5_Utank_Norminal_25 : 40|16@1+ (0.1,0) [0|6553.5] "V"  PC
 SG_ S2P_Cfg5_CSCType_25 : 56|4@1+ (1,0) [0|15] ""  PC

BO_ 2416373338 S2P_Cfg5__26: 8 SBMU
 SG_ S2P_Cfg5_SBMU_Add_26 : 0|8@1+ (1,0) [0|255] ""  PC
 SG_ S2P_Cfg5_ModuleParal_Num_26 : 8|8@1+ (1,0) [0|255] ""  PC
 SG_ S2P_Cfg5_CellSeries_Num_26 : 16|12@1+ (1,0) [0|4095] ""  PC
 SG_ S2P_Cfg5_Temps_Num_26 : 28|4@1+ (1,0) [0|15] ""  PC
 SG_ S2P_Cfg5_CSCs_Num_26 : 32|8@1+ (1,0) [0|255] ""  PC
 SG_ S2P_Cfg5_Utank_Norminal_26 : 40|16@1+ (0.1,0) [0|6553.5] "V"  PC
 SG_ S2P_Cfg5_CSCType_26 : 56|4@1+ (1,0) [0|15] ""  PC

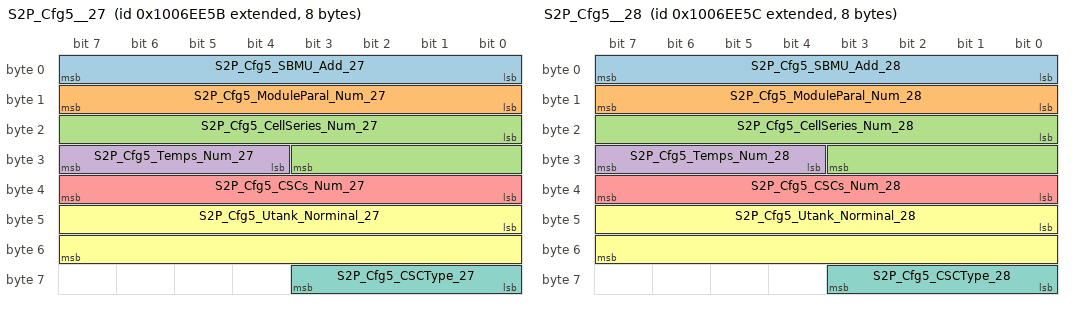
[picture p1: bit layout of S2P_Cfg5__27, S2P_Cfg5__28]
BO_ 2416373339 S2P_Cfg5__27: 8 SBMU
 SG_ S2P_Cfg5_SBMU_Add_27 : 0|8@1+ (1,0) [0|255] ""  PC
 SG_ S2P_Cfg5_ModuleParal_Num_27 : 8|8@1+ (1,0) [0|255] ""  PC
 SG_ S2P_Cfg5_CellSeries_Num_27 : 16|12@1+ (1,0) [0|4095] ""  PC
 SG_ S2P_Cfg5_Temps_Num_27 : 28|4@1+ (1,0) [0|15] ""  PC
 SG_ S2P_Cfg5_CSCs_Num_27 : 32|8@1+ (1,0) [0|255] ""  PC
 SG_ S2P_Cfg5_Utank_Norminal_27 : 40|16@1+ (0.1,0) [0|6553.5] "V"  PC
 SG_ S2P_Cfg5_CSCType_27 : 56|4@1+ (1,0) [0|15] ""  PC

BO_ 2416373340 S2P_Cfg5__28: 8 SBMU
 SG_ S2P_Cfg5_SBMU_Add_28 : 0|8@1+ (1,0) [0|255] ""  PC
 SG_ S2P_Cfg5_ModuleParal_Num_28 : 8|8@1+ (1,0) [0|255] ""  PC
 SG_ S2P_Cfg5_CellSeries_Num_28 : 16|12@1+ (1,0) [0|4095] ""  PC
 SG_ S2P_Cfg5_Temps_Num_28 : 28|4@1+ (1,0) [0|15] ""  PC
 SG_ S2P_Cfg5_CSCs_Num_28 : 32|8@1+ (1,0) [0|255] ""  PC
 SG_ S2P_Cfg5_Utank_Norminal_28 : 40|16@1+ (0.1,0) [0|6553.5] "V"  PC
 SG_ S2P_Cfg5_CSCType_28 : 56|4@1+ (1,0) [0|15] ""  PC

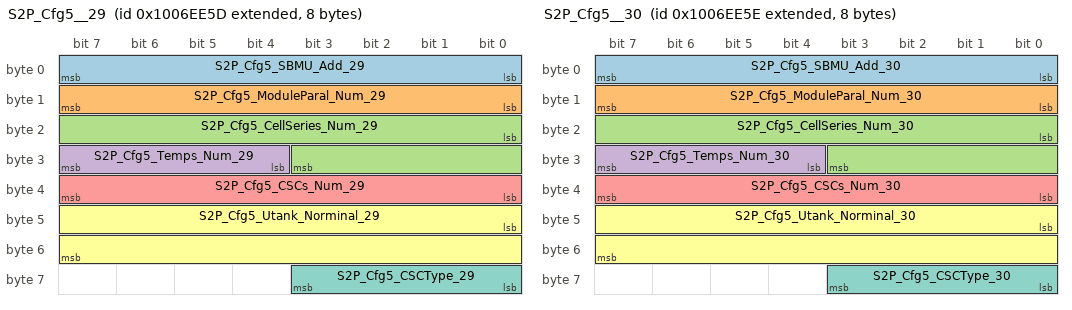
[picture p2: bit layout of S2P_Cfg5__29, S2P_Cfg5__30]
BO_ 2416373341 S2P_Cfg5__29: 8 SBMU
 SG_ S2P_Cfg5_SBMU_Add_29 : 0|8@1+ (1,0) [0|255] ""  PC
 SG_ S2P_Cfg5_ModuleParal_Num_29 : 8|8@1+ (1,0) [0|255] ""  PC
 SG_ S2P_Cfg5_CellSeries_Num_29 : 16|12@1+ (1,0) [0|4095] ""  PC
 SG_ S2P_Cfg5_Temps_Num_29 : 28|4@1+ (1,0) [0|15] ""  PC
 SG_ S2P_Cfg5_CSCs_Num_29 : 32|8@1+ (1,0) [0|255] ""  PC
 SG_ S2P_Cfg5_Utank_Norminal_29 : 40|16@1+ (0.1,0) [0|6553.5] "V"  PC
 SG_ S2P_Cfg5_CSCType_29 : 56|4@1+ (1,0) [0|15] ""  PC

BO_ 2416373342 S2P_Cfg5__30: 8 SBMU
 SG_ S2P_Cfg5_SBMU_Add_30 : 0|8@1+ (1,0) [0|255] ""  PC
 SG_ S2P_Cfg5_ModuleParal_Num_30 : 8|8@1+ (1,0) [0|255] ""  PC
 SG_ S2P_Cfg5_CellSeries_Num_30 : 16|12@1+ (1,0) [0|4095] ""  PC
 SG_ S2P_Cfg5_Temps_Num_30 : 28|4@1+ (1,0) [0|15] ""  PC
 SG_ S2P_Cfg5_CSCs_Num_30 : 32|8@1+ (1,0) [0|255] ""  PC
 SG_ S2P_Cfg5_Utank_Norminal_30 : 40|16@1+ (0.1,0) [0|6553.5] "V"  PC
 SG_ S2P_Cfg5_CSCType_30 : 56|4@1+ (1,0) [0|15] ""  PC

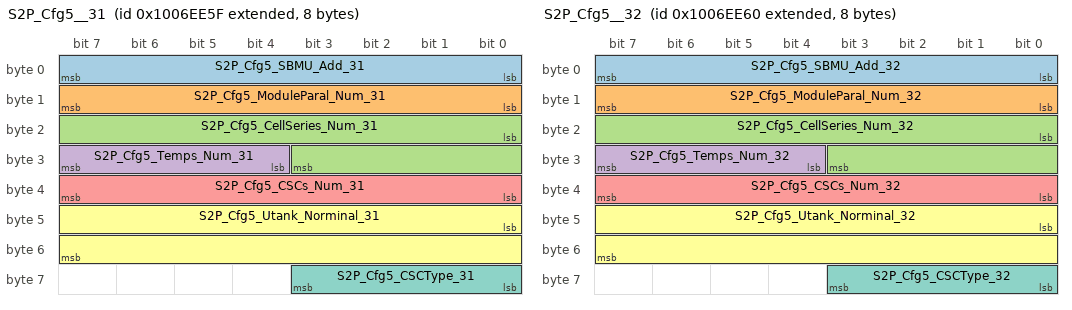
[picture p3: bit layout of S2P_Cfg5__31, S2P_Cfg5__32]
BO_ 2416373343 S2P_Cfg5__31: 8 SBMU
 SG_ S2P_Cfg5_SBMU_Add_31 : 0|8@1+ (1,0) [0|255] ""  PC
 SG_ S2P_Cfg5_ModuleParal_Num_31 : 8|8@1+ (1,0) [0|255] ""  PC
 SG_ S2P_Cfg5_CellSeries_Num_31 : 16|12@1+ (1,0) [0|4095] ""  PC
 SG_ S2P_Cfg5_Temps_Num_31 : 28|4@1+ (1,0) [0|15] ""  PC
 SG_ S2P_Cfg5_CSCs_Num_31 : 32|8@1+ (1,0) [0|255] ""  PC
 SG_ S2P_Cfg5_Utank_Norminal_31 : 40|16@1+ (0.1,0) [0|6553.5] "V"  PC
 SG_ S2P_Cfg5_CSCType_31 : 56|4@1+ (1,0) [0|15] ""  PC

BO_ 2416373344 S2P_Cfg5__32: 8 SBMU
 SG_ S2P_Cfg5_SBMU_Add_32 : 0|8@1+ (1,0) [0|255] ""  PC
 SG_ S2P_Cfg5_ModuleParal_Num_32 : 8|8@1+ (1,0) [0|255] ""  PC
 SG_ S2P_Cfg5_CellSeries_Num_32 : 16|12@1+ (1,0) [0|4095] ""  PC
 SG_ S2P_Cfg5_Temps_Num_32 : 28|4@1+ (1,0) [0|15] ""  PC
 SG_ S2P_Cfg5_CSCs_Num_32 : 32|8@1+ (1,0) [0|255] ""  PC
 SG_ S2P_Cfg5_Utank_Norminal_32 : 40|16@1+ (0.1,0) [0|6553.5] "V"  PC
 SG_ S2P_Cfg5_CSCType_32 : 56|4@1+ (1,0) [0|15] ""  PC

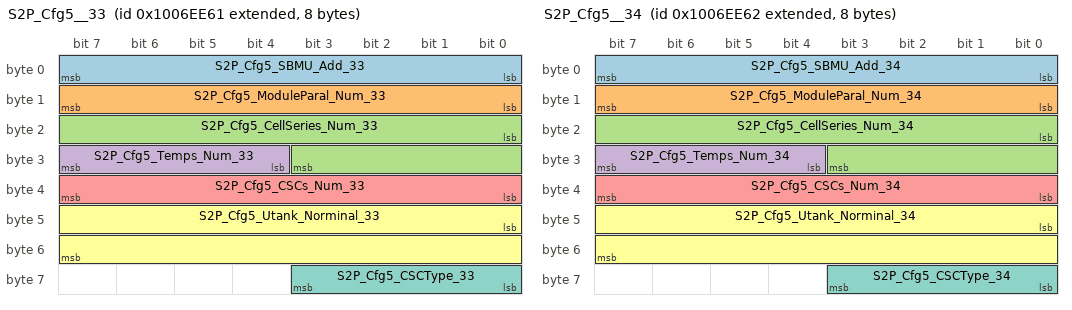
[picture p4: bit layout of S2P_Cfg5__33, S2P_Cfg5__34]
BO_ 2416373345 S2P_Cfg5__33: 8 SBMU
 SG_ S2P_Cfg5_SBMU_Add_33 : 0|8@1+ (1,0) [0|255] ""  PC
 SG_ S2P_Cfg5_ModuleParal_Num_33 : 8|8@1+ (1,0) [0|255] ""  PC
 SG_ S2P_Cfg5_CellSeries_Num_33 : 16|12@1+ (1,0) [0|4095] ""  PC
 SG_ S2P_Cfg5_Temps_Num_33 : 28|4@1+ (1,0) [0|15] ""  PC
 SG_ S2P_Cfg5_CSCs_Num_33 : 32|8@1+ (1,0) [0|255] ""  PC
 SG_ S2P_Cfg5_Utank_Norminal_33 : 40|16@1+ (0.1,0) [0|6553.5] "V"  PC
 SG_ S2P_Cfg5_CSCType_33 : 56|4@1+ (1,0) [0|15] ""  PC

BO_ 2416373346 S2P_Cfg5__34: 8 SBMU
 SG_ S2P_Cfg5_SBMU_Add_34 : 0|8@1+ (1,0) [0|255] ""  PC
 SG_ S2P_Cfg5_ModuleParal_Num_34 : 8|8@1+ (1,0) [0|255] ""  PC
 SG_ S2P_Cfg5_CellSeries_Num_34 : 16|12@1+ (1,0) [0|4095] ""  PC
 SG_ S2P_Cfg5_Temps_Num_34 : 28|4@1+ (1,0) [0|15] ""  PC
 SG_ S2P_Cfg5_CSCs_Num_34 : 32|8@1+ (1,0) [0|255] ""  PC
 SG_ S2P_Cfg5_Utank_Norminal_34 : 40|16@1+ (0.1,0) [0|6553.5] "V"  PC
 SG_ S2P_Cfg5_CSCType_34 : 56|4@1+ (1,0) [0|15] ""  PC

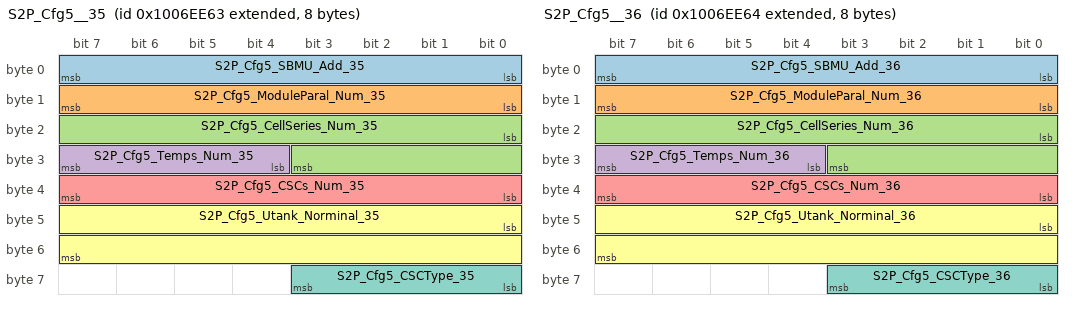
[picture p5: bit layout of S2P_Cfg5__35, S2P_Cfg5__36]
BO_ 2416373347 S2P_Cfg5__35: 8 SBMU
 SG_ S2P_Cfg5_SBMU_Add_35 : 0|8@1+ (1,0) [0|255] ""  PC
 SG_ S2P_Cfg5_ModuleParal_Num_35 : 8|8@1+ (1,0) [0|255] ""  PC
 SG_ S2P_Cfg5_CellSeries_Num_35 : 16|12@1+ (1,0) [0|4095] ""  PC
 SG_ S2P_Cfg5_Temps_Num_35 : 28|4@1+ (1,0) [0|15] ""  PC
 SG_ S2P_Cfg5_CSCs_Num_35 : 32|8@1+ (1,0) [0|255] ""  PC
 SG_ S2P_Cfg5_Utank_Norminal_35 : 40|16@1+ (0.1,0) [0|6553.5] "V"  PC
 SG_ S2P_Cfg5_CSCType_35 : 56|4@1+ (1,0) [0|15] ""  PC

BO_ 2416373348 S2P_Cfg5__36: 8 SBMU
 SG_ S2P_Cfg5_SBMU_Add_36 : 0|8@1+ (1,0) [0|255] ""  PC
 SG_ S2P_Cfg5_ModuleParal_Num_36 : 8|8@1+ (1,0) [0|255] ""  PC
 SG_ S2P_Cfg5_CellSeries_Num_36 : 16|12@1+ (1,0) [0|4095] ""  PC
 SG_ S2P_Cfg5_Temps_Num_36 : 28|4@1+ (1,0) [0|15] ""  PC
 SG_ S2P_Cfg5_CSCs_Num_36 : 32|8@1+ (1,0) [0|255] ""  PC
 SG_ S2P_Cfg5_Utank_Norminal_36 : 40|16@1+ (0.1,0) [0|6553.5] "V"  PC
 SG_ S2P_Cfg5_CSCType_36 : 56|4@1+ (1,0) [0|15] ""  PC

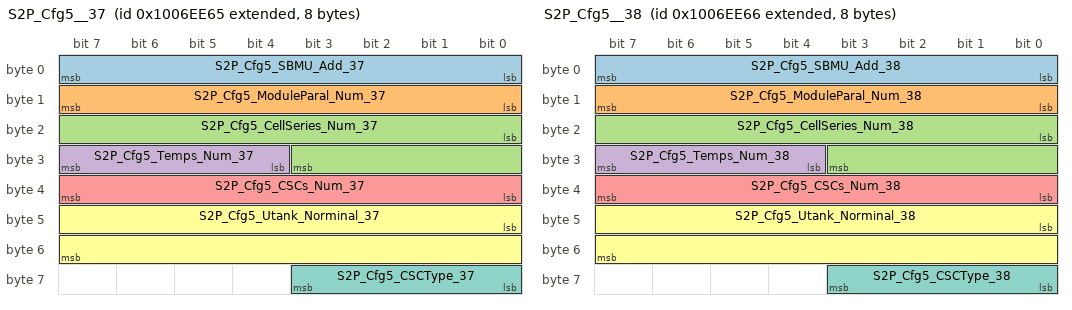
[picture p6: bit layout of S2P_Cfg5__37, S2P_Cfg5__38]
BO_ 2416373349 S2P_Cfg5__37: 8 SBMU
 SG_ S2P_Cfg5_SBMU_Add_37 : 0|8@1+ (1,0) [0|255] ""  PC
 SG_ S2P_Cfg5_ModuleParal_Num_37 : 8|8@1+ (1,0) [0|255] ""  PC
 SG_ S2P_Cfg5_CellSeries_Num_37 : 16|12@1+ (1,0) [0|4095] ""  PC
 SG_ S2P_Cfg5_Temps_Num_37 : 28|4@1+ (1,0) [0|15] ""  PC
 SG_ S2P_Cfg5_CSCs_Num_37 : 32|8@1+ (1,0) [0|255] ""  PC
 SG_ S2P_Cfg5_Utank_Norminal_37 : 40|16@1+ (0.1,0) [0|6553.5] "V"  PC
 SG_ S2P_Cfg5_CSCType_37 : 56|4@1+ (1,0) [0|15] ""  PC

BO_ 2416373350 S2P_Cfg5__38: 8 SBMU
 SG_ S2P_Cfg5_SBMU_Add_38 : 0|8@1+ (1,0) [0|255] ""  PC
 SG_ S2P_Cfg5_ModuleParal_Num_38 : 8|8@1+ (1,0) [0|255] ""  PC
 SG_ S2P_Cfg5_CellSeries_Num_38 : 16|12@1+ (1,0) [0|4095] ""  PC
 SG_ S2P_Cfg5_Temps_Num_38 : 28|4@1+ (1,0) [0|15] ""  PC
 SG_ S2P_Cfg5_CSCs_Num_38 : 32|8@1+ (1,0) [0|255] ""  PC
 SG_ S2P_Cfg5_Utank_Norminal_38 : 40|16@1+ (0.1,0) [0|6553.5] "V"  PC
 SG_ S2P_Cfg5_CSCType_38 : 56|4@1+ (1,0) [0|15] ""  PC

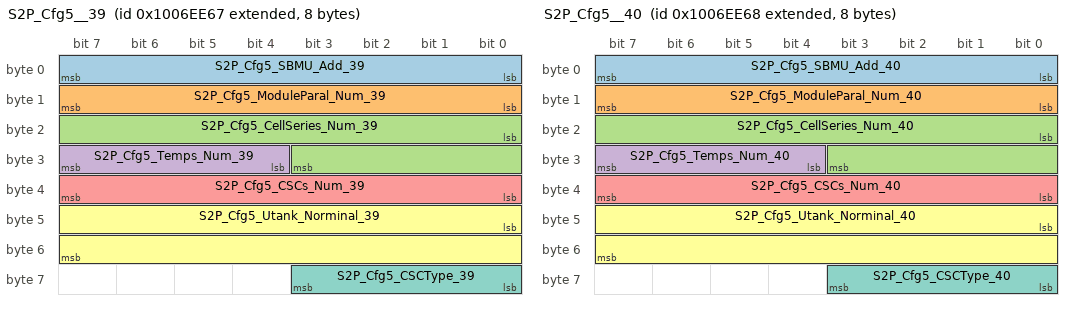
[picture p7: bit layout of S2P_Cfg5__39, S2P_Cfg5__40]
BO_ 2416373351 S2P_Cfg5__39: 8 SBMU
 SG_ S2P_Cfg5_SBMU_Add_39 : 0|8@1+ (1,0) [0|255] ""  PC
 SG_ S2P_Cfg5_ModuleParal_Num_39 : 8|8@1+ (1,0) [0|255] ""  PC
 SG_ S2P_Cfg5_CellSeries_Num_39 : 16|12@1+ (1,0) [0|4095] ""  PC
 SG_ S2P_Cfg5_Temps_Num_39 : 28|4@1+ (1,0) [0|15] ""  PC
 SG_ S2P_Cfg5_CSCs_Num_39 : 32|8@1+ (1,0) [0|255] ""  PC
 SG_ S2P_Cfg5_Utank_Norminal_39 : 40|16@1+ (0.1,0) [0|6553.5] "V"  PC
 SG_ S2P_Cfg5_CSCType_39 : 56|4@1+ (1,0) [0|15] ""  PC

BO_ 2416373352 S2P_Cfg5__40: 8 SBMU
 SG_ S2P_Cfg5_SBMU_Add_40 : 0|8@1+ (1,0) [0|255] ""  PC
 SG_ S2P_Cfg5_ModuleParal_Num_40 : 8|8@1+ (1,0) [0|255] ""  PC
 SG_ S2P_Cfg5_CellSeries_Num_40 : 16|12@1+ (1,0) [0|4095] ""  PC
 SG_ S2P_Cfg5_Temps_Num_40 : 28|4@1+ (1,0) [0|15] ""  PC
 SG_ S2P_Cfg5_CSCs_Num_40 : 32|8@1+ (1,0) [0|255] ""  PC
 SG_ S2P_Cfg5_Utank_Norminal_40 : 40|16@1+ (0.1,0) [0|6553.5] "V"  PC
 SG_ S2P_Cfg5_CSCType_40 : 56|4@1+ (1,0) [0|15] ""  PC

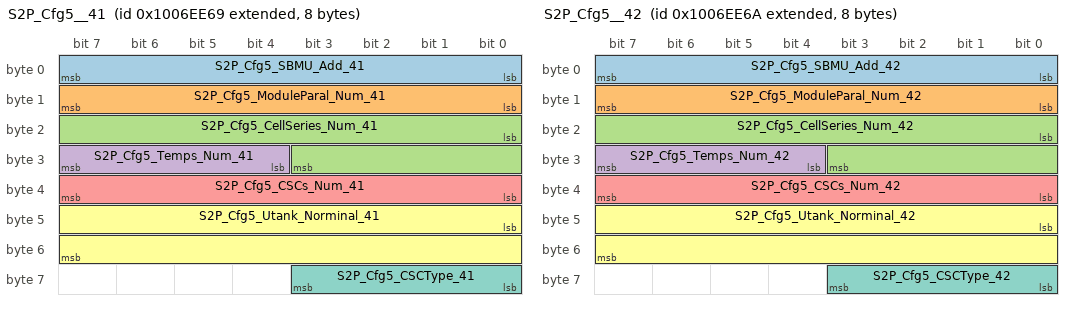
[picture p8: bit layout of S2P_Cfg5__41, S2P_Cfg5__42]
BO_ 2416373353 S2P_Cfg5__41: 8 SBMU
 SG_ S2P_Cfg5_SBMU_Add_41 : 0|8@1+ (1,0) [0|255] ""  PC
 SG_ S2P_Cfg5_ModuleParal_Num_41 : 8|8@1+ (1,0) [0|255] ""  PC
 SG_ S2P_Cfg5_CellSeries_Num_41 : 16|12@1+ (1,0) [0|4095] ""  PC
 SG_ S2P_Cfg5_Temps_Num_41 : 28|4@1+ (1,0) [0|15] ""  PC
 SG_ S2P_Cfg5_CSCs_Num_41 : 32|8@1+ (1,0) [0|255] ""  PC
 SG_ S2P_Cfg5_Utank_Norminal_41 : 40|16@1+ (0.1,0) [0|6553.5] "V"  PC
 SG_ S2P_Cfg5_CSCType_41 : 56|4@1+ (1,0) [0|15] ""  PC

BO_ 2416373354 S2P_Cfg5__42: 8 SBMU
 SG_ S2P_Cfg5_SBMU_Add_42 : 0|8@1+ (1,0) [0|255] ""  PC
 SG_ S2P_Cfg5_ModuleParal_Num_42 : 8|8@1+ (1,0) [0|255] ""  PC
 SG_ S2P_Cfg5_CellSeries_Num_42 : 16|12@1+ (1,0) [0|4095] ""  PC
 SG_ S2P_Cfg5_Temps_Num_42 : 28|4@1+ (1,0) [0|15] ""  PC
 SG_ S2P_Cfg5_CSCs_Num_42 : 32|8@1+ (1,0) [0|255] ""  PC
 SG_ S2P_Cfg5_Utank_Norminal_42 : 40|16@1+ (0.1,0) [0|6553.5] "V"  PC
 SG_ S2P_Cfg5_CSCType_42 : 56|4@1+ (1,0) [0|15] ""  PC

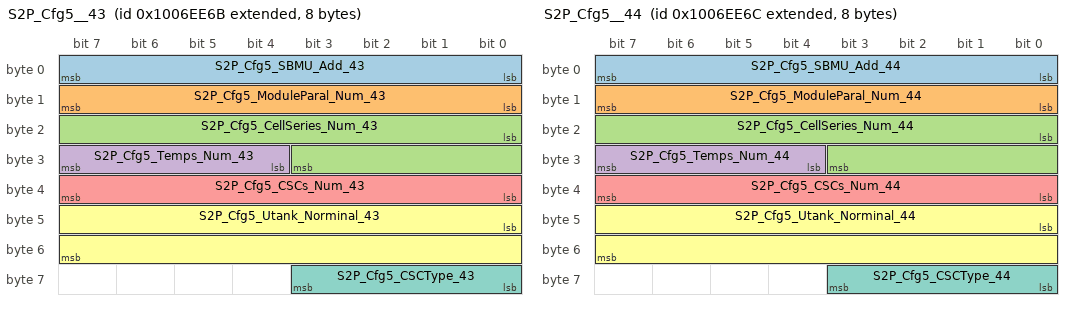
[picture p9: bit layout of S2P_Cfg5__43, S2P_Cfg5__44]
BO_ 2416373355 S2P_Cfg5__43: 8 SBMU
 SG_ S2P_Cfg5_SBMU_Add_43 : 0|8@1+ (1,0) [0|255] ""  PC
 SG_ S2P_Cfg5_ModuleParal_Num_43 : 8|8@1+ (1,0) [0|255] ""  PC
 SG_ S2P_Cfg5_CellSeries_Num_43 : 16|12@1+ (1,0) [0|4095] ""  PC
 SG_ S2P_Cfg5_Temps_Num_43 : 28|4@1+ (1,0) [0|15] ""  PC
 SG_ S2P_Cfg5_CSCs_Num_43 : 32|8@1+ (1,0) [0|255] ""  PC
 SG_ S2P_Cfg5_Utank_Norminal_43 : 40|16@1+ (0.1,0) [0|6553.5] "V"  PC
 SG_ S2P_Cfg5_CSCType_43 : 56|4@1+ (1,0) [0|15] ""  PC

BO_ 2416373356 S2P_Cfg5__44: 8 SBMU
 SG_ S2P_Cfg5_SBMU_Add_44 : 0|8@1+ (1,0) [0|255] ""  PC
 SG_ S2P_Cfg5_ModuleParal_Num_44 : 8|8@1+ (1,0) [0|255] ""  PC
 SG_ S2P_Cfg5_CellSeries_Num_44 : 16|12@1+ (1,0) [0|4095] ""  PC
 SG_ S2P_Cfg5_Temps_Num_44 : 28|4@1+ (1,0) [0|15] ""  PC
 SG_ S2P_Cfg5_CSCs_Num_44 : 32|8@1+ (1,0) [0|255] ""  PC
 SG_ S2P_Cfg5_Utank_Norminal_44 : 40|16@1+ (0.1,0) [0|6553.5] "V"  PC
 SG_ S2P_Cfg5_CSCType_44 : 56|4@1+ (1,0) [0|15] ""  PC

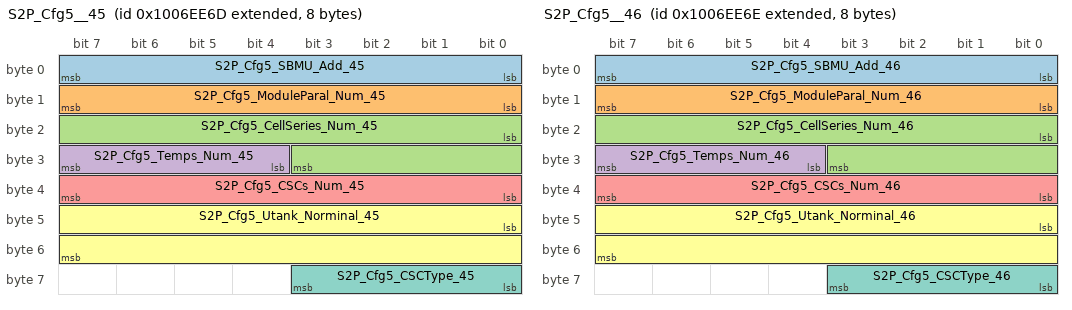
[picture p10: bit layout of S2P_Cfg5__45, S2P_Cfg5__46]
BO_ 2416373357 S2P_Cfg5__45: 8 SBMU
 SG_ S2P_Cfg5_SBMU_Add_45 : 0|8@1+ (1,0) [0|255] ""  PC
 SG_ S2P_Cfg5_ModuleParal_Num_45 : 8|8@1+ (1,0) [0|255] ""  PC
 SG_ S2P_Cfg5_CellSeries_Num_45 : 16|12@1+ (1,0) [0|4095] ""  PC
 SG_ S2P_Cfg5_Temps_Num_45 : 28|4@1+ (1,0) [0|15] ""  PC
 SG_ S2P_Cfg5_CSCs_Num_45 : 32|8@1+ (1,0) [0|255] ""  PC
 SG_ S2P_Cfg5_Utank_Norminal_45 : 40|16@1+ (0.1,0) [0|6553.5] "V"  PC
 SG_ S2P_Cfg5_CSCType_45 : 56|4@1+ (1,0) [0|15] ""  PC

BO_ 2416373358 S2P_Cfg5__46: 8 SBMU
 SG_ S2P_Cfg5_SBMU_Add_46 : 0|8@1+ (1,0) [0|255] ""  PC
 SG_ S2P_Cfg5_ModuleParal_Num_46 : 8|8@1+ (1,0) [0|255] ""  PC
 SG_ S2P_Cfg5_CellSeries_Num_46 : 16|12@1+ (1,0) [0|4095] ""  PC
 SG_ S2P_Cfg5_Temps_Num_46 : 28|4@1+ (1,0) [0|15] ""  PC
 SG_ S2P_Cfg5_CSCs_Num_46 : 32|8@1+ (1,0) [0|255] ""  PC
 SG_ S2P_Cfg5_Utank_Norminal_46 : 40|16@1+ (0.1,0) [0|6553.5] "V"  PC
 SG_ S2P_Cfg5_CSCType_46 : 56|4@1+ (1,0) [0|15] ""  PC

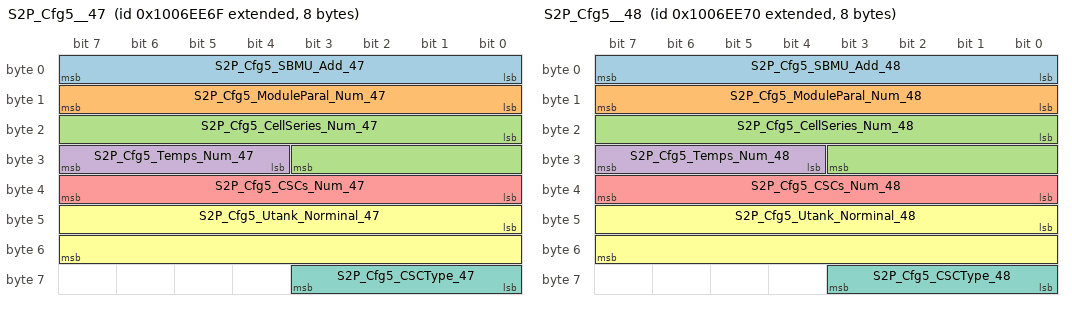
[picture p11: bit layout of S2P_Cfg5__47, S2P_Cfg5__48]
BO_ 2416373359 S2P_Cfg5__47: 8 SBMU
 SG_ S2P_Cfg5_SBMU_Add_47 : 0|8@1+ (1,0) [0|255] ""  PC
 SG_ S2P_Cfg5_ModuleParal_Num_47 : 8|8@1+ (1,0) [0|255] ""  PC
 SG_ S2P_Cfg5_CellSeries_Num_47 : 16|12@1+ (1,0) [0|4095] ""  PC
 SG_ S2P_Cfg5_Temps_Num_47 : 28|4@1+ (1,0) [0|15] ""  PC
 SG_ S2P_Cfg5_CSCs_Num_47 : 32|8@1+ (1,0) [0|255] ""  PC
 SG_ S2P_Cfg5_Utank_Norminal_47 : 40|16@1+ (0.1,0) [0|6553.5] "V"  PC
 SG_ S2P_Cfg5_CSCType_47 : 56|4@1+ (1,0) [0|15] ""  PC

BO_ 2416373360 S2P_Cfg5__48: 8 SBMU
 SG_ S2P_Cfg5_SBMU_Add_48 : 0|8@1+ (1,0) [0|255] ""  PC
 SG_ S2P_Cfg5_ModuleParal_Num_48 : 8|8@1+ (1,0) [0|255] ""  PC
 SG_ S2P_Cfg5_CellSeries_Num_48 : 16|12@1+ (1,0) [0|4095] ""  PC
 SG_ S2P_Cfg5_Temps_Num_48 : 28|4@1+ (1,0) [0|15] ""  PC
 SG_ S2P_Cfg5_CSCs_Num_48 : 32|8@1+ (1,0) [0|255] ""  PC
 SG_ S2P_Cfg5_Utank_Norminal_48 : 40|16@1+ (0.1,0) [0|6553.5] "V"  PC
 SG_ S2P_Cfg5_CSCType_48 : 56|4@1+ (1,0) [0|15] ""  PC

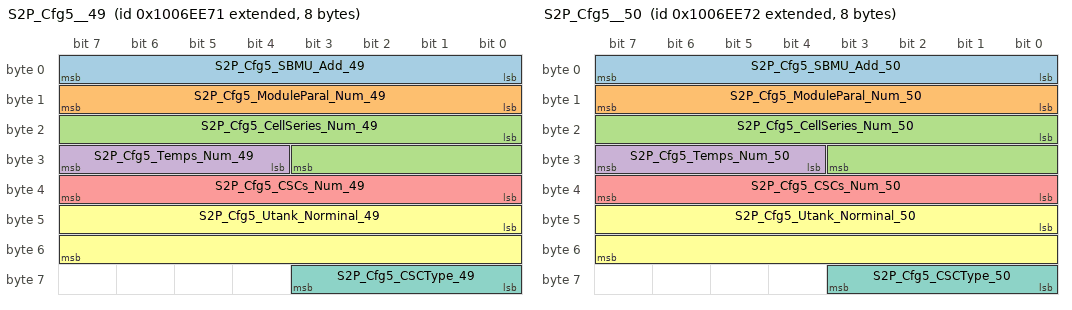
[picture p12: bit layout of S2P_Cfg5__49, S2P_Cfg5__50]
BO_ 2416373361 S2P_Cfg5__49: 8 SBMU
 SG_ S2P_Cfg5_SBMU_Add_49 : 0|8@1+ (1,0) [0|255] ""  PC
 SG_ S2P_Cfg5_ModuleParal_Num_49 : 8|8@1+ (1,0) [0|255] ""  PC
 SG_ S2P_Cfg5_CellSeries_Num_49 : 16|12@1+ (1,0) [0|4095] ""  PC
 SG_ S2P_Cfg5_Temps_Num_49 : 28|4@1+ (1,0) [0|15] ""  PC
 SG_ S2P_Cfg5_CSCs_Num_49 : 32|8@1+ (1,0) [0|255] ""  PC
 SG_ S2P_Cfg5_Utank_Norminal_49 : 40|16@1+ (0.1,0) [0|6553.5] "V"  PC
 SG_ S2P_Cfg5_CSCType_49 : 56|4@1+ (1,0) [0|15] ""  PC

BO_ 2416373362 S2P_Cfg5__50: 8 SBMU
 SG_ S2P_Cfg5_SBMU_Add_50 : 0|8@1+ (1,0) [0|255] ""  PC
 SG_ S2P_Cfg5_ModuleParal_Num_50 : 8|8@1+ (1,0) [0|255] ""  PC
 SG_ S2P_Cfg5_CellSeries_Num_50 : 16|12@1+ (1,0) [0|4095] ""  PC
 SG_ S2P_Cfg5_Temps_Num_50 : 28|4@1+ (1,0) [0|15] ""  PC
 SG_ S2P_Cfg5_CSCs_Num_50 : 32|8@1+ (1,0) [0|255] ""  PC
 SG_ S2P_Cfg5_Utank_Norminal_50 : 40|16@1+ (0.1,0) [0|6553.5] "V"  PC
 SG_ S2P_Cfg5_CSCType_50 : 56|4@1+ (1,0) [0|15] ""  PC

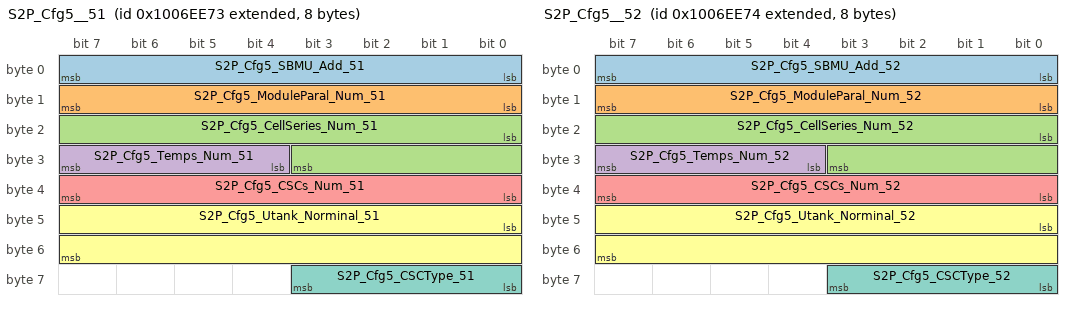
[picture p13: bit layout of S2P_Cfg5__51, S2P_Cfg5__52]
BO_ 2416373363 S2P_Cfg5__51: 8 SBMU
 SG_ S2P_Cfg5_SBMU_Add_51 : 0|8@1+ (1,0) [0|255] ""  PC
 SG_ S2P_Cfg5_ModuleParal_Num_51 : 8|8@1+ (1,0) [0|255] ""  PC
 SG_ S2P_Cfg5_CellSeries_Num_51 : 16|12@1+ (1,0) [0|4095] ""  PC
 SG_ S2P_Cfg5_Temps_Num_51 : 28|4@1+ (1,0) [0|15] ""  PC
 SG_ S2P_Cfg5_CSCs_Num_51 : 32|8@1+ (1,0) [0|255] ""  PC
 SG_ S2P_Cfg5_Utank_Norminal_51 : 40|16@1+ (0.1,0) [0|6553.5] "V"  PC
 SG_ S2P_Cfg5_CSCType_51 : 56|4@1+ (1,0) [0|15] ""  PC

BO_ 2416373364 S2P_Cfg5__52: 8 SBMU
 SG_ S2P_Cfg5_SBMU_Add_52 : 0|8@1+ (1,0) [0|255] ""  PC
 SG_ S2P_Cfg5_ModuleParal_Num_52 : 8|8@1+ (1,0) [0|255] ""  PC
 SG_ S2P_Cfg5_CellSeries_Num_52 : 16|12@1+ (1,0) [0|4095] ""  PC
 SG_ S2P_Cfg5_Temps_Num_52 : 28|4@1+ (1,0) [0|15] ""  PC
 SG_ S2P_Cfg5_CSCs_Num_52 : 32|8@1+ (1,0) [0|255] ""  PC
 SG_ S2P_Cfg5_Utank_Norminal_52 : 40|16@1+ (0.1,0) [0|6553.5] "V"  PC
 SG_ S2P_Cfg5_CSCType_52 : 56|4@1+ (1,0) [0|15] ""  PC

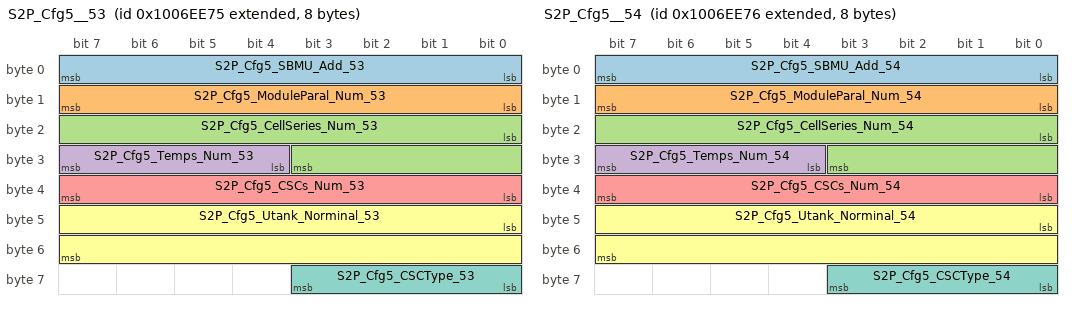
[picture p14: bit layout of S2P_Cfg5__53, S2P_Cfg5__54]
BO_ 2416373365 S2P_Cfg5__53: 8 SBMU
 SG_ S2P_Cfg5_SBMU_Add_53 : 0|8@1+ (1,0) [0|255] ""  PC
 SG_ S2P_Cfg5_ModuleParal_Num_53 : 8|8@1+ (1,0) [0|255] ""  PC
 SG_ S2P_Cfg5_CellSeries_Num_53 : 16|12@1+ (1,0) [0|4095] ""  PC
 SG_ S2P_Cfg5_Temps_Num_53 : 28|4@1+ (1,0) [0|15] ""  PC
 SG_ S2P_Cfg5_CSCs_Num_53 : 32|8@1+ (1,0) [0|255] ""  PC
 SG_ S2P_Cfg5_Utank_Norminal_53 : 40|16@1+ (0.1,0) [0|6553.5] "V"  PC
 SG_ S2P_Cfg5_CSCType_53 : 56|4@1+ (1,0) [0|15] ""  PC

BO_ 2416373366 S2P_Cfg5__54: 8 SBMU
 SG_ S2P_Cfg5_SBMU_Add_54 : 0|8@1+ (1,0) [0|255] ""  PC
 SG_ S2P_Cfg5_ModuleParal_Num_54 : 8|8@1+ (1,0) [0|255] ""  PC
 SG_ S2P_Cfg5_CellSeries_Num_54 : 16|12@1+ (1,0) [0|4095] ""  PC
 SG_ S2P_Cfg5_Temps_Num_54 : 28|4@1+ (1,0) [0|15] ""  PC
 SG_ S2P_Cfg5_CSCs_Num_54 : 32|8@1+ (1,0) [0|255] ""  PC
 SG_ S2P_Cfg5_Utank_Norminal_54 : 40|16@1+ (0.1,0) [0|6553.5] "V"  PC
 SG_ S2P_Cfg5_CSCType_54 : 56|4@1+ (1,0) [0|15] ""  PC

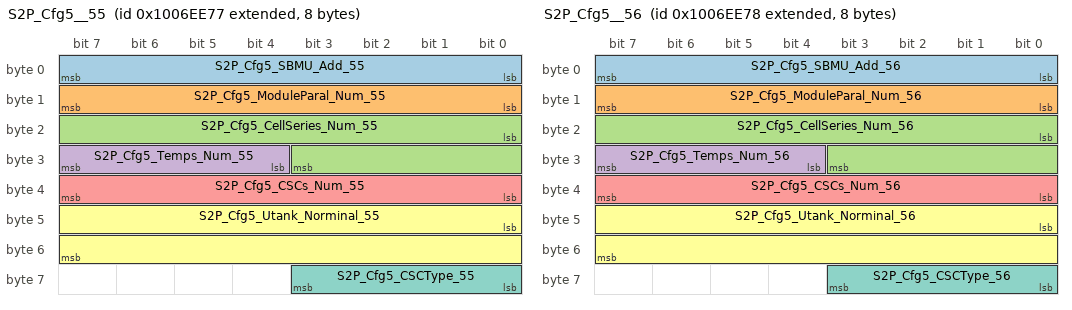
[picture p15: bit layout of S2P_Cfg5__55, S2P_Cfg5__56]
BO_ 2416373367 S2P_Cfg5__55: 8 SBMU
 SG_ S2P_Cfg5_SBMU_Add_55 : 0|8@1+ (1,0) [0|255] ""  PC
 SG_ S2P_Cfg5_ModuleParal_Num_55 : 8|8@1+ (1,0) [0|255] ""  PC
 SG_ S2P_Cfg5_CellSeries_Num_55 : 16|12@1+ (1,0) [0|4095] ""  PC
 SG_ S2P_Cfg5_Temps_Num_55 : 28|4@1+ (1,0) [0|15] ""  PC
 SG_ S2P_Cfg5_CSCs_Num_55 : 32|8@1+ (1,0) [0|255] ""  PC
 SG_ S2P_Cfg5_Utank_Norminal_55 : 40|16@1+ (0.1,0) [0|6553.5] "V"  PC
 SG_ S2P_Cfg5_CSCType_55 : 56|4@1+ (1,0) [0|15] ""  PC

BO_ 2416373368 S2P_Cfg5__56: 8 SBMU
 SG_ S2P_Cfg5_SBMU_Add_56 : 0|8@1+ (1,0) [0|255] ""  PC
 SG_ S2P_Cfg5_ModuleParal_Num_56 : 8|8@1+ (1,0) [0|255] ""  PC
 SG_ S2P_Cfg5_CellSeries_Num_56 : 16|12@1+ (1,0) [0|4095] ""  PC
 SG_ S2P_Cfg5_Temps_Num_56 : 28|4@1+ (1,0) [0|15] ""  PC
 SG_ S2P_Cfg5_CSCs_Num_56 : 32|8@1+ (1,0) [0|255] ""  PC
 SG_ S2P_Cfg5_Utank_Norminal_56 : 40|16@1+ (0.1,0) [0|6553.5] "V"  PC
 SG_ S2P_Cfg5_CSCType_56 : 56|4@1+ (1,0) [0|15] ""  PC

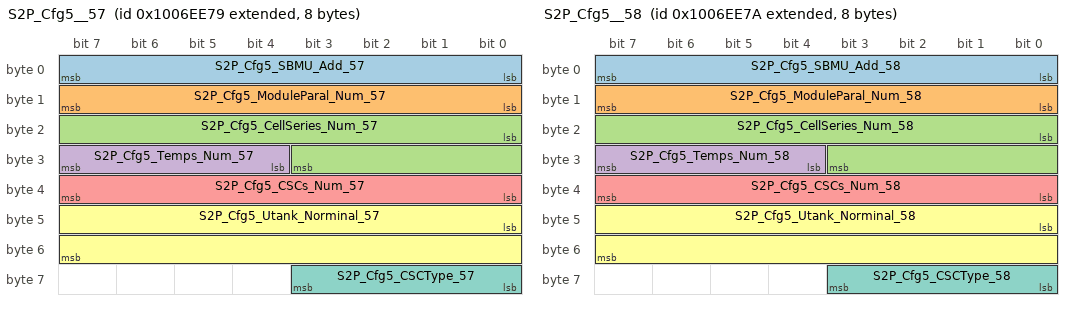
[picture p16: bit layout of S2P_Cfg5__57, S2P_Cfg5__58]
BO_ 2416373369 S2P_Cfg5__57: 8 SBMU
 SG_ S2P_Cfg5_SBMU_Add_57 : 0|8@1+ (1,0) [0|255] ""  PC
 SG_ S2P_Cfg5_ModuleParal_Num_57 : 8|8@1+ (1,0) [0|255] ""  PC
 SG_ S2P_Cfg5_CellSeries_Num_57 : 16|12@1+ (1,0) [0|4095] ""  PC
 SG_ S2P_Cfg5_Temps_Num_57 : 28|4@1+ (1,0) [0|15] ""  PC
 SG_ S2P_Cfg5_CSCs_Num_57 : 32|8@1+ (1,0) [0|255] ""  PC
 SG_ S2P_Cfg5_Utank_Norminal_57 : 40|16@1+ (0.1,0) [0|6553.5] "V"  PC
 SG_ S2P_Cfg5_CSCType_57 : 56|4@1+ (1,0) [0|15] ""  PC

BO_ 2416373370 S2P_Cfg5__58: 8 SBMU
 SG_ S2P_Cfg5_SBMU_Add_58 : 0|8@1+ (1,0) [0|255] ""  PC
 SG_ S2P_Cfg5_ModuleParal_Num_58 : 8|8@1+ (1,0) [0|255] ""  PC
 SG_ S2P_Cfg5_CellSeries_Num_58 : 16|12@1+ (1,0) [0|4095] ""  PC
 SG_ S2P_Cfg5_Temps_Num_58 : 28|4@1+ (1,0) [0|15] ""  PC
 SG_ S2P_Cfg5_CSCs_Num_58 : 32|8@1+ (1,0) [0|255] ""  PC
 SG_ S2P_Cfg5_Utank_Norminal_58 : 40|16@1+ (0.1,0) [0|6553.5] "V"  PC
 SG_ S2P_Cfg5_CSCType_58 : 56|4@1+ (1,0) [0|15] ""  PC

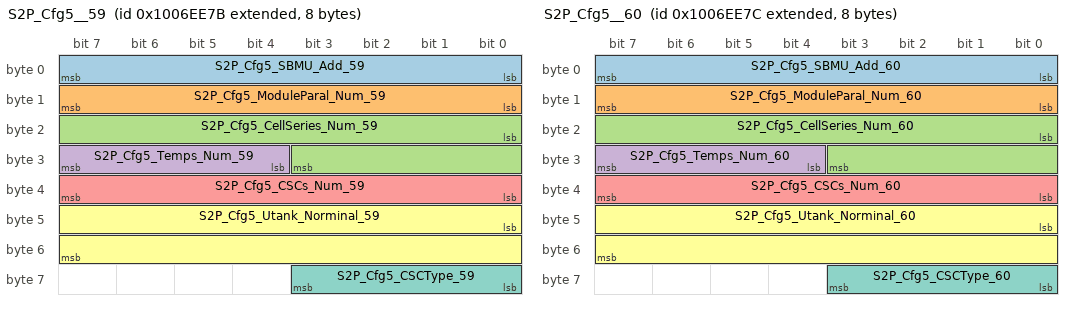
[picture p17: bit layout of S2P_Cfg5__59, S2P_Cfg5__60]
BO_ 2416373371 S2P_Cfg5__59: 8 SBMU
 SG_ S2P_Cfg5_SBMU_Add_59 : 0|8@1+ (1,0) [0|255] ""  PC
 SG_ S2P_Cfg5_ModuleParal_Num_59 : 8|8@1+ (1,0) [0|255] ""  PC
 SG_ S2P_Cfg5_CellSeries_Num_59 : 16|12@1+ (1,0) [0|4095] ""  PC
 SG_ S2P_Cfg5_Temps_Num_59 : 28|4@1+ (1,0) [0|15] ""  PC
 SG_ S2P_Cfg5_CSCs_Num_59 : 32|8@1+ (1,0) [0|255] ""  PC
 SG_ S2P_Cfg5_Utank_Norminal_59 : 40|16@1+ (0.1,0) [0|6553.5] "V"  PC
 SG_ S2P_Cfg5_CSCType_59 : 56|4@1+ (1,0) [0|15] ""  PC

BO_ 2416373372 S2P_Cfg5__60: 8 SBMU
 SG_ S2P_Cfg5_SBMU_Add_60 : 0|8@1+ (1,0) [0|255] ""  PC
 SG_ S2P_Cfg5_ModuleParal_Num_60 : 8|8@1+ (1,0) [0|255] ""  PC
 SG_ S2P_Cfg5_CellSeries_Num_60 : 16|12@1+ (1,0) [0|4095] ""  PC
 SG_ S2P_Cfg5_Temps_Num_60 : 28|4@1+ (1,0) [0|15] ""  PC
 SG_ S2P_Cfg5_CSCs_Num_60 : 32|8@1+ (1,0) [0|255] ""  PC
 SG_ S2P_Cfg5_Utank_Norminal_60 : 40|16@1+ (0.1,0) [0|6553.5] "V"  PC
 SG_ S2P_Cfg5_CSCType_60 : 56|4@1+ (1,0) [0|15] ""  PC

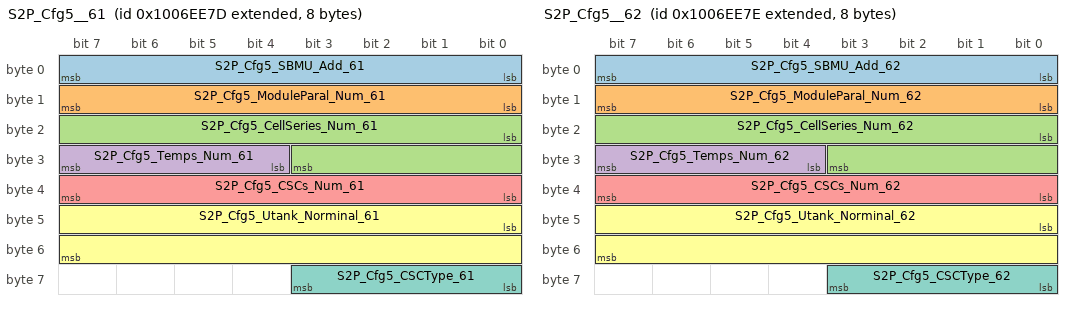
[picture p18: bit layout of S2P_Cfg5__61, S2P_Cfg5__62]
BO_ 2416373373 S2P_Cfg5__61: 8 SBMU
 SG_ S2P_Cfg5_SBMU_Add_61 : 0|8@1+ (1,0) [0|255] ""  PC
 SG_ S2P_Cfg5_ModuleParal_Num_61 : 8|8@1+ (1,0) [0|255] ""  PC
 SG_ S2P_Cfg5_CellSeries_Num_61 : 16|12@1+ (1,0) [0|4095] ""  PC
 SG_ S2P_Cfg5_Temps_Num_61 : 28|4@1+ (1,0) [0|15] ""  PC
 SG_ S2P_Cfg5_CSCs_Num_61 : 32|8@1+ (1,0) [0|255] ""  PC
 SG_ S2P_Cfg5_Utank_Norminal_61 : 40|16@1+ (0.1,0) [0|6553.5] "V"  PC
 SG_ S2P_Cfg5_CSCType_61 : 56|4@1+ (1,0) [0|15] ""  PC

BO_ 2416373374 S2P_Cfg5__62: 8 SBMU
 SG_ S2P_Cfg5_SBMU_Add_62 : 0|8@1+ (1,0) [0|255] ""  PC
 SG_ S2P_Cfg5_ModuleParal_Num_62 : 8|8@1+ (1,0) [0|255] ""  PC
 SG_ S2P_Cfg5_CellSeries_Num_62 : 16|12@1+ (1,0) [0|4095] ""  PC
 SG_ S2P_Cfg5_Temps_Num_62 : 28|4@1+ (1,0) [0|15] ""  PC
 SG_ S2P_Cfg5_CSCs_Num_62 : 32|8@1+ (1,0) [0|255] ""  PC
 SG_ S2P_Cfg5_Utank_Norminal_62 : 40|16@1+ (0.1,0) [0|6553.5] "V"  PC
 SG_ S2P_Cfg5_CSCType_62 : 56|4@1+ (1,0) [0|15] ""  PC

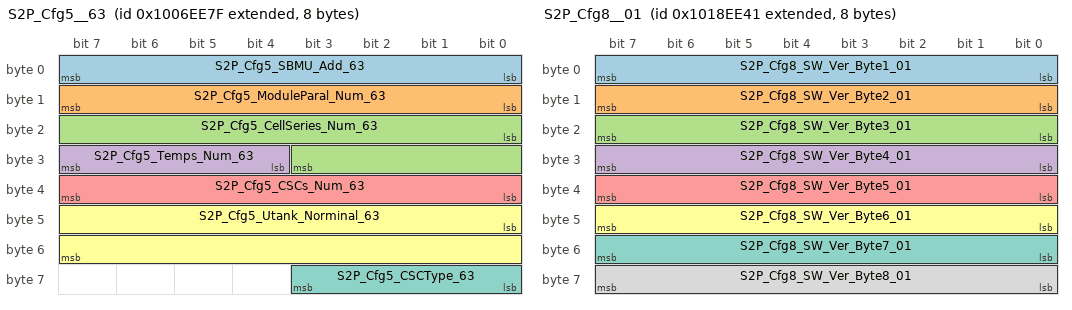
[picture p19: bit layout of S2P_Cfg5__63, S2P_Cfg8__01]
BO_ 2416373375 S2P_Cfg5__63: 8 SBMU
 SG_ S2P_Cfg5_SBMU_Add_63 : 0|8@1+ (1,0) [0|255] ""  PC
 SG_ S2P_Cfg5_ModuleParal_Num_63 : 8|8@1+ (1,0) [0|255] ""  PC
 SG_ S2P_Cfg5_CellSeries_Num_63 : 16|12@1+ (1,0) [0|4095] ""  PC
 SG_ S2P_Cfg5_Temps_Num_63 : 28|4@1+ (1,0) [0|15] ""  PC
 SG_ S2P_Cfg5_CSCs_Num_63 : 32|8@1+ (1,0) [0|255] ""  PC
 SG_ S2P_Cfg5_Utank_Norminal_63 : 40|16@1+ (0.1,0) [0|6553.5] "V"  PC
 SG_ S2P_Cfg5_CSCType_63 : 56|4@1+ (1,0) [0|15] ""  PC

BO_ 2416438849 S2P_Cfg6__01: 8 SBMU
 SG_ S2P_Cfg6_Ucell_Norminal_01 : 0|16@1+ (1,0) [0|65535] "mV"  PC
 SG_ S2P_Cfg6_Ccell_Norminal_01 : 16|16@1+ (0.1,0) [0|6553.5] "Ah"  PC

BO_ 2416438850 S2P_Cfg6__02: 8 SBMU
 SG_ S2P_Cfg6_Ucell_Norminal_02 : 0|16@1+ (1,0) [0|65535] "mV"  PC
 SG_ S2P_Cfg6_Ccell_Norminal_02 : 16|16@1+ (0.1,0) [0|6553.5] "Ah"  PC

BO_ 2416438851 S2P_Cfg6__03: 8 SBMU
 SG_ S2P_Cfg6_Ucell_Norminal_03 : 0|16@1+ (1,0) [0|65535] "mV"  PC
 SG_ S2P_Cfg6_Ccell_Norminal_03 : 16|16@1+ (0.1,0) [0|6553.5] "Ah"  PC

BO_ 2416438852 S2P_Cfg6__04: 8 SBMU
 SG_ S2P_Cfg6_Ucell_Norminal_04 : 0|16@1+ (1,0) [0|65535] "mV"  PC
 SG_ S2P_Cfg6_Ccell_Norminal_04 : 16|16@1+ (0.1,0) [0|6553.5] "Ah"  PC

BO_ 2416438853 S2P_Cfg6__05: 8 SBMU
 SG_ S2P_Cfg6_Ucell_Norminal_05 : 0|16@1+ (1,0) [0|65535] "mV"  PC
 SG_ S2P_Cfg6_Ccell_Norminal_05 : 16|16@1+ (0.1,0) [0|6553.5] "Ah"  PC

BO_ 2416438854 S2P_Cfg6__06: 8 SBMU
 SG_ S2P_Cfg6_Ucell_Norminal_06 : 0|16@1+ (1,0) [0|65535] "mV"  PC
 SG_ S2P_Cfg6_Ccell_Norminal_06 : 16|16@1+ (0.1,0) [0|6553.5] "Ah"  PC

BO_ 2416438855 S2P_Cfg6__07: 8 SBMU
 SG_ S2P_Cfg6_Ucell_Norminal_07 : 0|16@1+ (1,0) [0|65535] "mV"  PC
 SG_ S2P_Cfg6_Ccell_Norminal_07 : 16|16@1+ (0.1,0) [0|6553.5] "Ah"  PC

BO_ 2416438856 S2P_Cfg6__08: 8 SBMU
 SG_ S2P_Cfg6_Ucell_Norminal_08 : 0|16@1+ (1,0) [0|65535] "mV"  PC
 SG_ S2P_Cfg6_Ccell_Norminal_08 : 16|16@1+ (0.1,0) [0|6553.5] "Ah"  PC

BO_ 2416438857 S2P_Cfg6__09: 8 SBMU
 SG_ S2P_Cfg6_Ucell_Norminal_09 : 0|16@1+ (1,0) [0|65535] "mV"  PC
 SG_ S2P_Cfg6_Ccell_Norminal_09 : 16|16@1+ (0.1,0) [0|6553.5] "Ah"  PC

BO_ 2416438858 S2P_Cfg6__10: 8 SBMU
 SG_ S2P_Cfg6_Ucell_Norminal_10 : 0|16@1+ (1,0) [0|65535] "mV"  PC
 SG_ S2P_Cfg6_Ccell_Norminal_10 : 16|16@1+ (0.1,0) [0|6553.5] "Ah"  PC

BO_ 2416438859 S2P_Cfg6__11: 8 SBMU
 SG_ S2P_Cfg6_Ucell_Norminal_11 : 0|16@1+ (1,0) [0|65535] "mV"  PC
 SG_ S2P_Cfg6_Ccell_Norminal_11 : 16|16@1+ (0.1,0) [0|6553.5] "Ah"  PC

BO_ 2416438860 S2P_Cfg6__12: 8 SBMU
 SG_ S2P_Cfg6_Ucell_Norminal_12 : 0|16@1+ (1,0) [0|65535] "mV"  PC
 SG_ S2P_Cfg6_Ccell_Norminal_12 : 16|16@1+ (0.1,0) [0|6553.5] "Ah"  PC

BO_ 2416438861 S2P_Cfg6__13: 8 SBMU
 SG_ S2P_Cfg6_Ucell_Norminal_13 : 0|16@1+ (1,0) [0|65535] "mV"  PC
 SG_ S2P_Cfg6_Ccell_Norminal_13 : 16|16@1+ (0.1,0) [0|6553.5] "Ah"  PC

BO_ 2416438862 S2P_Cfg6__14: 8 SBMU
 SG_ S2P_Cfg6_Ucell_Norminal_14 : 0|16@1+ (1,0) [0|65535] "mV"  PC
 SG_ S2P_Cfg6_Ccell_Norminal_14 : 16|16@1+ (0.1,0) [0|6553.5] "Ah"  PC

BO_ 2416438863 S2P_Cfg6__15: 8 SBMU
 SG_ S2P_Cfg6_Ucell_Norminal_15 : 0|16@1+ (1,0) [0|65535] "mV"  PC
 SG_ S2P_Cfg6_Ccell_Norminal_15 : 16|16@1+ (0.1,0) [0|6553.5] "Ah"  PC

BO_ 2416438864 S2P_Cfg6__16: 8 SBMU
 SG_ S2P_Cfg6_Ucell_Norminal_16 : 0|16@1+ (1,0) [0|65535] "mV"  PC
 SG_ S2P_Cfg6_Ccell_Norminal_16 : 16|16@1+ (0.1,0) [0|6553.5] "Ah"  PC

BO_ 2416438865 S2P_Cfg6__17: 8 SBMU
 SG_ S2P_Cfg6_Ucell_Norminal_17 : 0|16@1+ (1,0) [0|65535] "mV"  PC
 SG_ S2P_Cfg6_Ccell_Norminal_17 : 16|16@1+ (0.1,0) [0|6553.5] "Ah"  PC

BO_ 2416438866 S2P_Cfg6__18: 8 SBMU
 SG_ S2P_Cfg6_Ucell_Norminal_18 : 0|16@1+ (1,0) [0|65535] "mV"  PC
 SG_ S2P_Cfg6_Ccell_Norminal_18 : 16|16@1+ (0.1,0) [0|6553.5] "Ah"  PC

BO_ 2416438867 S2P_Cfg6__19: 8 SBMU
 SG_ S2P_Cfg6_Ucell_Norminal_19 : 0|16@1+ (1,0) [0|65535] "mV"  PC
 SG_ S2P_Cfg6_Ccell_Norminal_19 : 16|16@1+ (0.1,0) [0|6553.5] "Ah"  PC

BO_ 2416438868 S2P_Cfg6__20: 8 SBMU
 SG_ S2P_Cfg6_Ucell_Norminal_20 : 0|16@1+ (1,0) [0|65535] "mV"  PC
 SG_ S2P_Cfg6_Ccell_Norminal_20 : 16|16@1+ (0.1,0) [0|6553.5] "Ah"  PC

BO_ 2416438869 S2P_Cfg6__21: 8 SBMU
 SG_ S2P_Cfg6_Ucell_Norminal_21 : 0|16@1+ (1,0) [0|65535] "mV"  PC
 SG_ S2P_Cfg6_Ccell_Norminal_21 : 16|16@1+ (0.1,0) [0|6553.5] "Ah"  PC

BO_ 2416438870 S2P_Cfg6__22: 8 SBMU
 SG_ S2P_Cfg6_Ucell_Norminal_22 : 0|16@1+ (1,0) [0|65535] "mV"  PC
 SG_ S2P_Cfg6_Ccell_Norminal_22 : 16|16@1+ (0.1,0) [0|6553.5] "Ah"  PC

BO_ 2416438871 S2P_Cfg6__23: 8 SBMU
 SG_ S2P_Cfg6_Ucell_Norminal_23 : 0|16@1+ (1,0) [0|65535] "mV"  PC
 SG_ S2P_Cfg6_Ccell_Norminal_23 : 16|16@1+ (0.1,0) [0|6553.5] "Ah"  PC

BO_ 2416438872 S2P_Cfg6__24: 8 SBMU
 SG_ S2P_Cfg6_Ucell_Norminal_24 : 0|16@1+ (1,0) [0|65535] "mV"  PC
 SG_ S2P_Cfg6_Ccell_Norminal_24 : 16|16@1+ (0.1,0) [0|6553.5] "Ah"  PC

BO_ 2416438873 S2P_Cfg6__25: 8 SBMU
 SG_ S2P_Cfg6_Ucell_Norminal_25 : 0|16@1+ (1,0) [0|65535] "mV"  PC
 SG_ S2P_Cfg6_Ccell_Norminal_25 : 16|16@1+ (0.1,0) [0|6553.5] "Ah"  PC

BO_ 2416438874 S2P_Cfg6__26: 8 SBMU
 SG_ S2P_Cfg6_Ucell_Norminal_26 : 0|16@1+ (1,0) [0|65535] "mV"  PC
 SG_ S2P_Cfg6_Ccell_Norminal_26 : 16|16@1+ (0.1,0) [0|6553.5] "Ah"  PC

BO_ 2416438875 S2P_Cfg6__27: 8 SBMU
 SG_ S2P_Cfg6_Ucell_Norminal_27 : 0|16@1+ (1,0) [0|65535] "mV"  PC
 SG_ S2P_Cfg6_Ccell_Norminal_27 : 16|16@1+ (0.1,0) [0|6553.5] "Ah"  PC

BO_ 2416438876 S2P_Cfg6__28: 8 SBMU
 SG_ S2P_Cfg6_Ucell_Norminal_28 : 0|16@1+ (1,0) [0|65535] "mV"  PC
 SG_ S2P_Cfg6_Ccell_Norminal_28 : 16|16@1+ (0.1,0) [0|6553.5] "Ah"  PC

BO_ 2416438877 S2P_Cfg6__29: 8 SBMU
 SG_ S2P_Cfg6_Ucell_Norminal_29 : 0|16@1+ (1,0) [0|65535] "mV"  PC
 SG_ S2P_Cfg6_Ccell_Norminal_29 : 16|16@1+ (0.1,0) [0|6553.5] "Ah"  PC

BO_ 2416438878 S2P_Cfg6__30: 8 SBMU
 SG_ S2P_Cfg6_Ucell_Norminal_30 : 0|16@1+ (1,0) [0|65535] "mV"  PC
 SG_ S2P_Cfg6_Ccell_Norminal_30 : 16|16@1+ (0.1,0) [0|6553.5] "Ah"  PC

BO_ 2416438879 S2P_Cfg6__31: 8 SBMU
 SG_ S2P_Cfg6_Ucell_Norminal_31 : 0|16@1+ (1,0) [0|65535] "mV"  PC
 SG_ S2P_Cfg6_Ccell_Norminal_31 : 16|16@1+ (0.1,0) [0|6553.5] "Ah"  PC

BO_ 2416438880 S2P_Cfg6__32: 8 SBMU
 SG_ S2P_Cfg6_Ucell_Norminal_32 : 0|16@1+ (1,0) [0|65535] "mV"  PC
 SG_ S2P_Cfg6_Ccell_Norminal_32 : 16|16@1+ (0.1,0) [0|6553.5] "Ah"  PC

BO_ 2416438881 S2P_Cfg6__33: 8 SBMU
 SG_ S2P_Cfg6_Ucell_Norminal_33 : 0|16@1+ (1,0) [0|65535] "mV"  PC
 SG_ S2P_Cfg6_Ccell_Norminal_33 : 16|16@1+ (0.1,0) [0|6553.5] "Ah"  PC

BO_ 2416438882 S2P_Cfg6__34: 8 SBMU
 SG_ S2P_Cfg6_Ucell_Norminal_34 : 0|16@1+ (1,0) [0|65535] "mV"  PC
 SG_ S2P_Cfg6_Ccell_Norminal_34 : 16|16@1+ (0.1,0) [0|6553.5] "Ah"  PC

BO_ 2416438883 S2P_Cfg6__35: 8 SBMU
 SG_ S2P_Cfg6_Ucell_Norminal_35 : 0|16@1+ (1,0) [0|65535] "mV"  PC
 SG_ S2P_Cfg6_Ccell_Norminal_35 : 16|16@1+ (0.1,0) [0|6553.5] "Ah"  PC

BO_ 2416438884 S2P_Cfg6__36: 8 SBMU
 SG_ S2P_Cfg6_Ucell_Norminal_36 : 0|16@1+ (1,0) [0|65535] "mV"  PC
 SG_ S2P_Cfg6_Ccell_Norminal_36 : 16|16@1+ (0.1,0) [0|6553.5] "Ah"  PC

BO_ 2416438885 S2P_Cfg6__37: 8 SBMU
 SG_ S2P_Cfg6_Ucell_Norminal_37 : 0|16@1+ (1,0) [0|65535] "mV"  PC
 SG_ S2P_Cfg6_Ccell_Norminal_37 : 16|16@1+ (0.1,0) [0|6553.5] "Ah"  PC

BO_ 2416438886 S2P_Cfg6__38: 8 SBMU
 SG_ S2P_Cfg6_Ucell_Norminal_38 : 0|16@1+ (1,0) [0|65535] "mV"  PC
 SG_ S2P_Cfg6_Ccell_Norminal_38 : 16|16@1+ (0.1,0) [0|6553.5] "Ah"  PC

BO_ 2416438887 S2P_Cfg6__39: 8 SBMU
 SG_ S2P_Cfg6_Ucell_Norminal_39 : 0|16@1+ (1,0) [0|65535] "mV"  PC
 SG_ S2P_Cfg6_Ccell_Norminal_39 : 16|16@1+ (0.1,0) [0|6553.5] "Ah"  PC

BO_ 2416438888 S2P_Cfg6__40: 8 SBMU
 SG_ S2P_Cfg6_Ucell_Norminal_40 : 0|16@1+ (1,0) [0|65535] "mV"  PC
 SG_ S2P_Cfg6_Ccell_Norminal_40 : 16|16@1+ (0.1,0) [0|6553.5] "Ah"  PC

BO_ 2416438889 S2P_Cfg6__41: 8 SBMU
 SG_ S2P_Cfg6_Ucell_Norminal_41 : 0|16@1+ (1,0) [0|65535] "mV"  PC
 SG_ S2P_Cfg6_Ccell_Norminal_41 : 16|16@1+ (0.1,0) [0|6553.5] "Ah"  PC

BO_ 2416438890 S2P_Cfg6__42: 8 SBMU
 SG_ S2P_Cfg6_Ucell_Norminal_42 : 0|16@1+ (1,0) [0|65535] "mV"  PC
 SG_ S2P_Cfg6_Ccell_Norminal_42 : 16|16@1+ (0.1,0) [0|6553.5] "Ah"  PC

BO_ 2416438891 S2P_Cfg6__43: 8 SBMU
 SG_ S2P_Cfg6_Ucell_Norminal_43 : 0|16@1+ (1,0) [0|65535] "mV"  PC
 SG_ S2P_Cfg6_Ccell_Norminal_43 : 16|16@1+ (0.1,0) [0|6553.5] "Ah"  PC

BO_ 2416438892 S2P_Cfg6__44: 8 SBMU
 SG_ S2P_Cfg6_Ucell_Norminal_44 : 0|16@1+ (1,0) [0|65535] "mV"  PC
 SG_ S2P_Cfg6_Ccell_Norminal_44 : 16|16@1+ (0.1,0) [0|6553.5] "Ah"  PC

BO_ 2416438893 S2P_Cfg6__45: 8 SBMU
 SG_ S2P_Cfg6_Ucell_Norminal_45 : 0|16@1+ (1,0) [0|65535] "mV"  PC
 SG_ S2P_Cfg6_Ccell_Norminal_45 : 16|16@1+ (0.1,0) [0|6553.5] "Ah"  PC

BO_ 2416438894 S2P_Cfg6__46: 8 SBMU
 SG_ S2P_Cfg6_Ucell_Norminal_46 : 0|16@1+ (1,0) [0|65535] "mV"  PC
 SG_ S2P_Cfg6_Ccell_Norminal_46 : 16|16@1+ (0.1,0) [0|6553.5] "Ah"  PC

BO_ 2416438895 S2P_Cfg6__47: 8 SBMU
 SG_ S2P_Cfg6_Ucell_Norminal_47 : 0|16@1+ (1,0) [0|65535] "mV"  PC
 SG_ S2P_Cfg6_Ccell_Norminal_47 : 16|16@1+ (0.1,0) [0|6553.5] "Ah"  PC

BO_ 2416438896 S2P_Cfg6__48: 8 SBMU
 SG_ S2P_Cfg6_Ucell_Norminal_48 : 0|16@1+ (1,0) [0|65535] "mV"  PC
 SG_ S2P_Cfg6_Ccell_Norminal_48 : 16|16@1+ (0.1,0) [0|6553.5] "Ah"  PC

BO_ 2416438897 S2P_Cfg6__49: 8 SBMU
 SG_ S2P_Cfg6_Ucell_Norminal_49 : 0|16@1+ (1,0) [0|65535] "mV"  PC
 SG_ S2P_Cfg6_Ccell_Norminal_49 : 16|16@1+ (0.1,0) [0|6553.5] "Ah"  PC

BO_ 2416438898 S2P_Cfg6__50: 8 SBMU
 SG_ S2P_Cfg6_Ucell_Norminal_50 : 0|16@1+ (1,0) [0|65535] "mV"  PC
 SG_ S2P_Cfg6_Ccell_Norminal_50 : 16|16@1+ (0.1,0) [0|6553.5] "Ah"  PC

BO_ 2416438899 S2P_Cfg6__51: 8 SBMU
 SG_ S2P_Cfg6_Ucell_Norminal_51 : 0|16@1+ (1,0) [0|65535] "mV"  PC
 SG_ S2P_Cfg6_Ccell_Norminal_51 : 16|16@1+ (0.1,0) [0|6553.5] "Ah"  PC

BO_ 2416438900 S2P_Cfg6__52: 8 SBMU
 SG_ S2P_Cfg6_Ucell_Norminal_52 : 0|16@1+ (1,0) [0|65535] "mV"  PC
 SG_ S2P_Cfg6_Ccell_Norminal_52 : 16|16@1+ (0.1,0) [0|6553.5] "Ah"  PC

BO_ 2416438901 S2P_Cfg6__53: 8 SBMU
 SG_ S2P_Cfg6_Ucell_Norminal_53 : 0|16@1+ (1,0) [0|65535] "mV"  PC
 SG_ S2P_Cfg6_Ccell_Norminal_53 : 16|16@1+ (0.1,0) [0|6553.5] "Ah"  PC

BO_ 2416438902 S2P_Cfg6__54: 8 SBMU
 SG_ S2P_Cfg6_Ucell_Norminal_54 : 0|16@1+ (1,0) [0|65535] "mV"  PC
 SG_ S2P_Cfg6_Ccell_Norminal_54 : 16|16@1+ (0.1,0) [0|6553.5] "Ah"  PC

BO_ 2416438903 S2P_Cfg6__55: 8 SBMU
 SG_ S2P_Cfg6_Ucell_Norminal_55 : 0|16@1+ (1,0) [0|65535] "mV"  PC
 SG_ S2P_Cfg6_Ccell_Norminal_55 : 16|16@1+ (0.1,0) [0|6553.5] "Ah"  PC

BO_ 2416438904 S2P_Cfg6__56: 8 SBMU
 SG_ S2P_Cfg6_Ucell_Norminal_56 : 0|16@1+ (1,0) [0|65535] "mV"  PC
 SG_ S2P_Cfg6_Ccell_Norminal_56 : 16|16@1+ (0.1,0) [0|6553.5] "Ah"  PC

BO_ 2416438905 S2P_Cfg6__57: 8 SBMU
 SG_ S2P_Cfg6_Ucell_Norminal_57 : 0|16@1+ (1,0) [0|65535] "mV"  PC
 SG_ S2P_Cfg6_Ccell_Norminal_57 : 16|16@1+ (0.1,0) [0|6553.5] "Ah"  PC

BO_ 2416438906 S2P_Cfg6__58: 8 SBMU
 SG_ S2P_Cfg6_Ucell_Norminal_58 : 0|16@1+ (1,0) [0|65535] "mV"  PC
 SG_ S2P_Cfg6_Ccell_Norminal_58 : 16|16@1+ (0.1,0) [0|6553.5] "Ah"  PC

BO_ 2416438907 S2P_Cfg6__59: 8 SBMU
 SG_ S2P_Cfg6_Ucell_Norminal_59 : 0|16@1+ (1,0) [0|65535] "mV"  PC
 SG_ S2P_Cfg6_Ccell_Norminal_59 : 16|16@1+ (0.1,0) [0|6553.5] "Ah"  PC

BO_ 2416438908 S2P_Cfg6__60: 8 SBMU
 SG_ S2P_Cfg6_Ucell_Norminal_60 : 0|16@1+ (1,0) [0|65535] "mV"  PC
 SG_ S2P_Cfg6_Ccell_Norminal_60 : 16|16@1+ (0.1,0) [0|6553.5] "Ah"  PC

BO_ 2416438909 S2P_Cfg6__61: 8 SBMU
 SG_ S2P_Cfg6_Ucell_Norminal_61 : 0|16@1+ (1,0) [0|65535] "mV"  PC
 SG_ S2P_Cfg6_Ccell_Norminal_61 : 16|16@1+ (0.1,0) [0|6553.5] "Ah"  PC

BO_ 2416438910 S2P_Cfg6__62: 8 SBMU
 SG_ S2P_Cfg6_Ucell_Norminal_62 : 0|16@1+ (1,0) [0|65535] "mV"  PC
 SG_ S2P_Cfg6_Ccell_Norminal_62 : 16|16@1+ (0.1,0) [0|6553.5] "Ah"  PC

BO_ 2416438911 S2P_Cfg6__63: 8 SBMU
 SG_ S2P_Cfg6_Ucell_Norminal_63 : 0|16@1+ (1,0) [0|65535] "mV"  PC
 SG_ S2P_Cfg6_Ccell_Norminal_63 : 16|16@1+ (0.1,0) [0|6553.5] "Ah"  PC

BO_ 2416504385 S2P_Cfg7__01: 8 SBMU
 SG_ S2P_Cfg7_CSCCellSeries_Num_01 : 0|8@1+ (1,0) [0|255] ""  PC
 SG_ S2P_Cfg7_CSCCellParal_Num_01 : 8|4@1+ (1,0) [0|15] ""  PC
 SG_ S2P_Cfg7_CSCTempsNum_01 : 12|6@1+ (1,0) [0|63] ""  PC
 SG_ S2P_Cfg7_CSCCellTempsNum_01 : 18|6@1+ (1,0) [0|63] ""  PC

BO_ 2416504386 S2P_Cfg7__02: 8 SBMU
 SG_ S2P_Cfg7_CSCCellSeries_Num_02 : 0|8@1+ (1,0) [0|255] ""  PC
 SG_ S2P_Cfg7_CSCCellParal_Num_02 : 8|4@1+ (1,0) [0|15] ""  PC
 SG_ S2P_Cfg7_CSCTempsNum_02 : 12|6@1+ (1,0) [0|63] ""  PC
 SG_ S2P_Cfg7_CSCCellTempsNum_02 : 18|6@1+ (1,0) [0|63] ""  PC

BO_ 2416504387 S2P_Cfg7__03: 8 SBMU
 SG_ S2P_Cfg7_CSCCellSeries_Num_03 : 0|8@1+ (1,0) [0|255] ""  PC
 SG_ S2P_Cfg7_CSCCellParal_Num_03 : 8|4@1+ (1,0) [0|15] ""  PC
 SG_ S2P_Cfg7_CSCTempsNum_03 : 12|6@1+ (1,0) [0|63] ""  PC
 SG_ S2P_Cfg7_CSCCellTempsNum_03 : 18|6@1+ (1,0) [0|63] ""  PC

BO_ 2416504388 S2P_Cfg7__04: 8 SBMU
 SG_ S2P_Cfg7_CSCCellSeries_Num_04 : 0|8@1+ (1,0) [0|255] ""  PC
 SG_ S2P_Cfg7_CSCCellParal_Num_04 : 8|4@1+ (1,0) [0|15] ""  PC
 SG_ S2P_Cfg7_CSCTempsNum_04 : 12|6@1+ (1,0) [0|63] ""  PC
 SG_ S2P_Cfg7_CSCCellTempsNum_04 : 18|6@1+ (1,0) [0|63] ""  PC

BO_ 2416504389 S2P_Cfg7__05: 8 SBMU
 SG_ S2P_Cfg7_CSCCellSeries_Num_05 : 0|8@1+ (1,0) [0|255] ""  PC
 SG_ S2P_Cfg7_CSCCellParal_Num_05 : 8|4@1+ (1,0) [0|15] ""  PC
 SG_ S2P_Cfg7_CSCTempsNum_05 : 12|6@1+ (1,0) [0|63] ""  PC
 SG_ S2P_Cfg7_CSCCellTempsNum_05 : 18|6@1+ (1,0) [0|63] ""  PC

BO_ 2416504390 S2P_Cfg7__06: 8 SBMU
 SG_ S2P_Cfg7_CSCCellSeries_Num_06 : 0|8@1+ (1,0) [0|255] ""  PC
 SG_ S2P_Cfg7_CSCCellParal_Num_06 : 8|4@1+ (1,0) [0|15] ""  PC
 SG_ S2P_Cfg7_CSCTempsNum_06 : 12|6@1+ (1,0) [0|63] ""  PC
 SG_ S2P_Cfg7_CSCCellTempsNum_06 : 18|6@1+ (1,0) [0|63] ""  PC

BO_ 2416504391 S2P_Cfg7__07: 8 SBMU
 SG_ S2P_Cfg7_CSCCellSeries_Num_07 : 0|8@1+ (1,0) [0|255] ""  PC
 SG_ S2P_Cfg7_CSCCellParal_Num_07 : 8|4@1+ (1,0) [0|15] ""  PC
 SG_ S2P_Cfg7_CSCTempsNum_07 : 12|6@1+ (1,0) [0|63] ""  PC
 SG_ S2P_Cfg7_CSCCellTempsNum_07 : 18|6@1+ (1,0) [0|63] ""  PC

BO_ 2416504392 S2P_Cfg7__08: 8 SBMU
 SG_ S2P_Cfg7_CSCCellSeries_Num_08 : 0|8@1+ (1,0) [0|255] ""  PC
 SG_ S2P_Cfg7_CSCCellParal_Num_08 : 8|4@1+ (1,0) [0|15] ""  PC
 SG_ S2P_Cfg7_CSCTempsNum_08 : 12|6@1+ (1,0) [0|63] ""  PC
 SG_ S2P_Cfg7_CSCCellTempsNum_08 : 18|6@1+ (1,0) [0|63] ""  PC

BO_ 2416504393 S2P_Cfg7__09: 8 SBMU
 SG_ S2P_Cfg7_CSCCellSeries_Num_09 : 0|8@1+ (1,0) [0|255] ""  PC
 SG_ S2P_Cfg7_CSCCellParal_Num_09 : 8|4@1+ (1,0) [0|15] ""  PC
 SG_ S2P_Cfg7_CSCTempsNum_09 : 12|6@1+ (1,0) [0|63] ""  PC
 SG_ S2P_Cfg7_CSCCellTempsNum_09 : 18|6@1+ (1,0) [0|63] ""  PC

BO_ 2416504394 S2P_Cfg7__10: 8 SBMU
 SG_ S2P_Cfg7_CSCCellSeries_Num_10 : 0|8@1+ (1,0) [0|255] ""  PC
 SG_ S2P_Cfg7_CSCCellParal_Num_10 : 8|4@1+ (1,0) [0|15] ""  PC
 SG_ S2P_Cfg7_CSCTempsNum_10 : 12|6@1+ (1,0) [0|63] ""  PC
 SG_ S2P_Cfg7_CSCCellTempsNum_10 : 18|6@1+ (1,0) [0|63] ""  PC

BO_ 2416504395 S2P_Cfg7__11: 8 SBMU
 SG_ S2P_Cfg7_CSCCellSeries_Num_11 : 0|8@1+ (1,0) [0|255] ""  PC
 SG_ S2P_Cfg7_CSCCellParal_Num_11 : 8|4@1+ (1,0) [0|15] ""  PC
 SG_ S2P_Cfg7_CSCTempsNum_11 : 12|6@1+ (1,0) [0|63] ""  PC
 SG_ S2P_Cfg7_CSCCellTempsNum_11 : 18|6@1+ (1,0) [0|63] ""  PC

BO_ 2416504396 S2P_Cfg7__12: 8 SBMU
 SG_ S2P_Cfg7_CSCCellSeries_Num_12 : 0|8@1+ (1,0) [0|255] ""  PC
 SG_ S2P_Cfg7_CSCCellParal_Num_12 : 8|4@1+ (1,0) [0|15] ""  PC
 SG_ S2P_Cfg7_CSCTempsNum_12 : 12|6@1+ (1,0) [0|63] ""  PC
 SG_ S2P_Cfg7_CSCCellTempsNum_12 : 18|6@1+ (1,0) [0|63] ""  PC

BO_ 2416504397 S2P_Cfg7__13: 8 SBMU
 SG_ S2P_Cfg7_CSCCellSeries_Num_13 : 0|8@1+ (1,0) [0|255] ""  PC
 SG_ S2P_Cfg7_CSCCellParal_Num_13 : 8|4@1+ (1,0) [0|15] ""  PC
 SG_ S2P_Cfg7_CSCTempsNum_13 : 12|6@1+ (1,0) [0|63] ""  PC
 SG_ S2P_Cfg7_CSCCellTempsNum_13 : 18|6@1+ (1,0) [0|63] ""  PC

BO_ 2416504398 S2P_Cfg7__14: 8 SBMU
 SG_ S2P_Cfg7_CSCCellSeries_Num_14 : 0|8@1+ (1,0) [0|255] ""  PC
 SG_ S2P_Cfg7_CSCCellParal_Num_14 : 8|4@1+ (1,0) [0|15] ""  PC
 SG_ S2P_Cfg7_CSCTempsNum_14 : 12|6@1+ (1,0) [0|63] ""  PC
 SG_ S2P_Cfg7_CSCCellTempsNum_14 : 18|6@1+ (1,0) [0|63] ""  PC

BO_ 2416504399 S2P_Cfg7__15: 8 SBMU
 SG_ S2P_Cfg7_CSCCellSeries_Num_15 : 0|8@1+ (1,0) [0|255] ""  PC
 SG_ S2P_Cfg7_CSCCellParal_Num_15 : 8|4@1+ (1,0) [0|15] ""  PC
 SG_ S2P_Cfg7_CSCTempsNum_15 : 12|6@1+ (1,0) [0|63] ""  PC
 SG_ S2P_Cfg7_CSCCellTempsNum_15 : 18|6@1+ (1,0) [0|63] ""  PC

BO_ 2416504400 S2P_Cfg7__16: 8 SBMU
 SG_ S2P_Cfg7_CSCCellSeries_Num_16 : 0|8@1+ (1,0) [0|255] ""  PC
 SG_ S2P_Cfg7_CSCCellParal_Num_16 : 8|4@1+ (1,0) [0|15] ""  PC
 SG_ S2P_Cfg7_CSCTempsNum_16 : 12|6@1+ (1,0) [0|63] ""  PC
 SG_ S2P_Cfg7_CSCCellTempsNum_16 : 18|6@1+ (1,0) [0|63] ""  PC

BO_ 2416504401 S2P_Cfg7__17: 8 SBMU
 SG_ S2P_Cfg7_CSCCellSeries_Num_17 : 0|8@1+ (1,0) [0|255] ""  PC
 SG_ S2P_Cfg7_CSCCellParal_Num_17 : 8|4@1+ (1,0) [0|15] ""  PC
 SG_ S2P_Cfg7_CSCTempsNum_17 : 12|6@1+ (1,0) [0|63] ""  PC
 SG_ S2P_Cfg7_CSCCellTempsNum_17 : 18|6@1+ (1,0) [0|63] ""  PC

BO_ 2416504402 S2P_Cfg7__18: 8 SBMU
 SG_ S2P_Cfg7_CSCCellSeries_Num_18 : 0|8@1+ (1,0) [0|255] ""  PC
 SG_ S2P_Cfg7_CSCCellParal_Num_18 : 8|4@1+ (1,0) [0|15] ""  PC
 SG_ S2P_Cfg7_CSCTempsNum_18 : 12|6@1+ (1,0) [0|63] ""  PC
 SG_ S2P_Cfg7_CSCCellTempsNum_18 : 18|6@1+ (1,0) [0|63] ""  PC

BO_ 2416504403 S2P_Cfg7__19: 8 SBMU
 SG_ S2P_Cfg7_CSCCellSeries_Num_19 : 0|8@1+ (1,0) [0|255] ""  PC
 SG_ S2P_Cfg7_CSCCellParal_Num_19 : 8|4@1+ (1,0) [0|15] ""  PC
 SG_ S2P_Cfg7_CSCTempsNum_19 : 12|6@1+ (1,0) [0|63] ""  PC
 SG_ S2P_Cfg7_CSCCellTempsNum_19 : 18|6@1+ (1,0) [0|63] ""  PC

BO_ 2416504404 S2P_Cfg7__20: 8 SBMU
 SG_ S2P_Cfg7_CSCCellSeries_Num_20 : 0|8@1+ (1,0) [0|255] ""  PC
 SG_ S2P_Cfg7_CSCCellParal_Num_20 : 8|4@1+ (1,0) [0|15] ""  PC
 SG_ S2P_Cfg7_CSCTempsNum_20 : 12|6@1+ (1,0) [0|63] ""  PC
 SG_ S2P_Cfg7_CSCCellTempsNum_20 : 18|6@1+ (1,0) [0|63] ""  PC

BO_ 2416504405 S2P_Cfg7__21: 8 SBMU
 SG_ S2P_Cfg7_CSCCellSeries_Num_21 : 0|8@1+ (1,0) [0|255] ""  PC
 SG_ S2P_Cfg7_CSCCellParal_Num_21 : 8|4@1+ (1,0) [0|15] ""  PC
 SG_ S2P_Cfg7_CSCTempsNum_21 : 12|6@1+ (1,0) [0|63] ""  PC
 SG_ S2P_Cfg7_CSCCellTempsNum_21 : 18|6@1+ (1,0) [0|63] ""  PC

BO_ 2416504406 S2P_Cfg7__22: 8 SBMU
 SG_ S2P_Cfg7_CSCCellSeries_Num_22 : 0|8@1+ (1,0) [0|255] ""  PC
 SG_ S2P_Cfg7_CSCCellParal_Num_22 : 8|4@1+ (1,0) [0|15] ""  PC
 SG_ S2P_Cfg7_CSCTempsNum_22 : 12|6@1+ (1,0) [0|63] ""  PC
 SG_ S2P_Cfg7_CSCCellTempsNum_22 : 18|6@1+ (1,0) [0|63] ""  PC

BO_ 2416504407 S2P_Cfg7__23: 8 SBMU
 SG_ S2P_Cfg7_CSCCellSeries_Num_23 : 0|8@1+ (1,0) [0|255] ""  PC
 SG_ S2P_Cfg7_CSCCellParal_Num_23 : 8|4@1+ (1,0) [0|15] ""  PC
 SG_ S2P_Cfg7_CSCTempsNum_23 : 12|6@1+ (1,0) [0|63] ""  PC
 SG_ S2P_Cfg7_CSCCellTempsNum_23 : 18|6@1+ (1,0) [0|63] ""  PC

BO_ 2416504408 S2P_Cfg7__24: 8 SBMU
 SG_ S2P_Cfg7_CSCCellSeries_Num_24 : 0|8@1+ (1,0) [0|255] ""  PC
 SG_ S2P_Cfg7_CSCCellParal_Num_24 : 8|4@1+ (1,0) [0|15] ""  PC
 SG_ S2P_Cfg7_CSCTempsNum_24 : 12|6@1+ (1,0) [0|63] ""  PC
 SG_ S2P_Cfg7_CSCCellTempsNum_24 : 18|6@1+ (1,0) [0|63] ""  PC

BO_ 2416504409 S2P_Cfg7__25: 8 SBMU
 SG_ S2P_Cfg7_CSCCellSeries_Num_25 : 0|8@1+ (1,0) [0|255] ""  PC
 SG_ S2P_Cfg7_CSCCellParal_Num_25 : 8|4@1+ (1,0) [0|15] ""  PC
 SG_ S2P_Cfg7_CSCTempsNum_25 : 12|6@1+ (1,0) [0|63] ""  PC
 SG_ S2P_Cfg7_CSCCellTempsNum_25 : 18|6@1+ (1,0) [0|63] ""  PC

BO_ 2416504410 S2P_Cfg7__26: 8 SBMU
 SG_ S2P_Cfg7_CSCCellSeries_Num_26 : 0|8@1+ (1,0) [0|255] ""  PC
 SG_ S2P_Cfg7_CSCCellParal_Num_26 : 8|4@1+ (1,0) [0|15] ""  PC
 SG_ S2P_Cfg7_CSCTempsNum_26 : 12|6@1+ (1,0) [0|63] ""  PC
 SG_ S2P_Cfg7_CSCCellTempsNum_26 : 18|6@1+ (1,0) [0|63] ""  PC

BO_ 2416504411 S2P_Cfg7__27: 8 SBMU
 SG_ S2P_Cfg7_CSCCellSeries_Num_27 : 0|8@1+ (1,0) [0|255] ""  PC
 SG_ S2P_Cfg7_CSCCellParal_Num_27 : 8|4@1+ (1,0) [0|15] ""  PC
 SG_ S2P_Cfg7_CSCTempsNum_27 : 12|6@1+ (1,0) [0|63] ""  PC
 SG_ S2P_Cfg7_CSCCellTempsNum_27 : 18|6@1+ (1,0) [0|63] ""  PC

BO_ 2416504412 S2P_Cfg7__28: 8 SBMU
 SG_ S2P_Cfg7_CSCCellSeries_Num_28 : 0|8@1+ (1,0) [0|255] ""  PC
 SG_ S2P_Cfg7_CSCCellParal_Num_28 : 8|4@1+ (1,0) [0|15] ""  PC
 SG_ S2P_Cfg7_CSCTempsNum_28 : 12|6@1+ (1,0) [0|63] ""  PC
 SG_ S2P_Cfg7_CSCCellTempsNum_28 : 18|6@1+ (1,0) [0|63] ""  PC

BO_ 2416504413 S2P_Cfg7__29: 8 SBMU
 SG_ S2P_Cfg7_CSCCellSeries_Num_29 : 0|8@1+ (1,0) [0|255] ""  PC
 SG_ S2P_Cfg7_CSCCellParal_Num_29 : 8|4@1+ (1,0) [0|15] ""  PC
 SG_ S2P_Cfg7_CSCTempsNum_29 : 12|6@1+ (1,0) [0|63] ""  PC
 SG_ S2P_Cfg7_CSCCellTempsNum_29 : 18|6@1+ (1,0) [0|63] ""  PC

BO_ 2416504414 S2P_Cfg7__30: 8 SBMU
 SG_ S2P_Cfg7_CSCCellSeries_Num_30 : 0|8@1+ (1,0) [0|255] ""  PC
 SG_ S2P_Cfg7_CSCCellParal_Num_30 : 8|4@1+ (1,0) [0|15] ""  PC
 SG_ S2P_Cfg7_CSCTempsNum_30 : 12|6@1+ (1,0) [0|63] ""  PC
 SG_ S2P_Cfg7_CSCCellTempsNum_30 : 18|6@1+ (1,0) [0|63] ""  PC

BO_ 2416504415 S2P_Cfg7__31: 8 SBMU
 SG_ S2P_Cfg7_CSCCellSeries_Num_31 : 0|8@1+ (1,0) [0|255] ""  PC
 SG_ S2P_Cfg7_CSCCellParal_Num_31 : 8|4@1+ (1,0) [0|15] ""  PC
 SG_ S2P_Cfg7_CSCTempsNum_31 : 12|6@1+ (1,0) [0|63] ""  PC
 SG_ S2P_Cfg7_CSCCellTempsNum_31 : 18|6@1+ (1,0) [0|63] ""  PC

BO_ 2416504416 S2P_Cfg7__32: 8 SBMU
 SG_ S2P_Cfg7_CSCCellSeries_Num_32 : 0|8@1+ (1,0) [0|255] ""  PC
 SG_ S2P_Cfg7_CSCCellParal_Num_32 : 8|4@1+ (1,0) [0|15] ""  PC
 SG_ S2P_Cfg7_CSCTempsNum_32 : 12|6@1+ (1,0) [0|63] ""  PC
 SG_ S2P_Cfg7_CSCCellTempsNum_32 : 18|6@1+ (1,0) [0|63] ""  PC

BO_ 2416504417 S2P_Cfg7__33: 8 SBMU
 SG_ S2P_Cfg7_CSCCellSeries_Num_33 : 0|8@1+ (1,0) [0|255] ""  PC
 SG_ S2P_Cfg7_CSCCellParal_Num_33 : 8|4@1+ (1,0) [0|15] ""  PC
 SG_ S2P_Cfg7_CSCTempsNum_33 : 12|6@1+ (1,0) [0|63] ""  PC
 SG_ S2P_Cfg7_CSCCellTempsNum_33 : 18|6@1+ (1,0) [0|63] ""  PC

BO_ 2416504418 S2P_Cfg7__34: 8 SBMU
 SG_ S2P_Cfg7_CSCCellSeries_Num_34 : 0|8@1+ (1,0) [0|255] ""  PC
 SG_ S2P_Cfg7_CSCCellParal_Num_34 : 8|4@1+ (1,0) [0|15] ""  PC
 SG_ S2P_Cfg7_CSCTempsNum_34 : 12|6@1+ (1,0) [0|63] ""  PC
 SG_ S2P_Cfg7_CSCCellTempsNum_34 : 18|6@1+ (1,0) [0|63] ""  PC

BO_ 2416504419 S2P_Cfg7__35: 8 SBMU
 SG_ S2P_Cfg7_CSCCellSeries_Num_35 : 0|8@1+ (1,0) [0|255] ""  PC
 SG_ S2P_Cfg7_CSCCellParal_Num_35 : 8|4@1+ (1,0) [0|15] ""  PC
 SG_ S2P_Cfg7_CSCTempsNum_35 : 12|6@1+ (1,0) [0|63] ""  PC
 SG_ S2P_Cfg7_CSCCellTempsNum_35 : 18|6@1+ (1,0) [0|63] ""  PC

BO_ 2416504420 S2P_Cfg7__36: 8 SBMU
 SG_ S2P_Cfg7_CSCCellSeries_Num_36 : 0|8@1+ (1,0) [0|255] ""  PC
 SG_ S2P_Cfg7_CSCCellParal_Num_36 : 8|4@1+ (1,0) [0|15] ""  PC
 SG_ S2P_Cfg7_CSCTempsNum_36 : 12|6@1+ (1,0) [0|63] ""  PC
 SG_ S2P_Cfg7_CSCCellTempsNum_36 : 18|6@1+ (1,0) [0|63] ""  PC

BO_ 2416504421 S2P_Cfg7__37: 8 SBMU
 SG_ S2P_Cfg7_CSCCellSeries_Num_37 : 0|8@1+ (1,0) [0|255] ""  PC
 SG_ S2P_Cfg7_CSCCellParal_Num_37 : 8|4@1+ (1,0) [0|15] ""  PC
 SG_ S2P_Cfg7_CSCTempsNum_37 : 12|6@1+ (1,0) [0|63] ""  PC
 SG_ S2P_Cfg7_CSCCellTempsNum_37 : 18|6@1+ (1,0) [0|63] ""  PC

BO_ 2416504422 S2P_Cfg7__38: 8 SBMU
 SG_ S2P_Cfg7_CSCCellSeries_Num_38 : 0|8@1+ (1,0) [0|255] ""  PC
 SG_ S2P_Cfg7_CSCCellParal_Num_38 : 8|4@1+ (1,0) [0|15] ""  PC
 SG_ S2P_Cfg7_CSCTempsNum_38 : 12|6@1+ (1,0) [0|63] ""  PC
 SG_ S2P_Cfg7_CSCCellTempsNum_38 : 18|6@1+ (1,0) [0|63] ""  PC

BO_ 2416504423 S2P_Cfg7__39: 8 SBMU
 SG_ S2P_Cfg7_CSCCellSeries_Num_39 : 0|8@1+ (1,0) [0|255] ""  PC
 SG_ S2P_Cfg7_CSCCellParal_Num_39 : 8|4@1+ (1,0) [0|15] ""  PC
 SG_ S2P_Cfg7_CSCTempsNum_39 : 12|6@1+ (1,0) [0|63] ""  PC
 SG_ S2P_Cfg7_CSCCellTempsNum_39 : 18|6@1+ (1,0) [0|63] ""  PC

BO_ 2416504424 S2P_Cfg7__40: 8 SBMU
 SG_ S2P_Cfg7_CSCCellSeries_Num_40 : 0|8@1+ (1,0) [0|255] ""  PC
 SG_ S2P_Cfg7_CSCCellParal_Num_40 : 8|4@1+ (1,0) [0|15] ""  PC
 SG_ S2P_Cfg7_CSCTempsNum_40 : 12|6@1+ (1,0) [0|63] ""  PC
 SG_ S2P_Cfg7_CSCCellTempsNum_40 : 18|6@1+ (1,0) [0|63] ""  PC

BO_ 2416504425 S2P_Cfg7__41: 8 SBMU
 SG_ S2P_Cfg7_CSCCellSeries_Num_41 : 0|8@1+ (1,0) [0|255] ""  PC
 SG_ S2P_Cfg7_CSCCellParal_Num_41 : 8|4@1+ (1,0) [0|15] ""  PC
 SG_ S2P_Cfg7_CSCTempsNum_41 : 12|6@1+ (1,0) [0|63] ""  PC
 SG_ S2P_Cfg7_CSCCellTempsNum_41 : 18|6@1+ (1,0) [0|63] ""  PC

BO_ 2416504426 S2P_Cfg7__42: 8 SBMU
 SG_ S2P_Cfg7_CSCCellSeries_Num_42 : 0|8@1+ (1,0) [0|255] ""  PC
 SG_ S2P_Cfg7_CSCCellParal_Num_42 : 8|4@1+ (1,0) [0|15] ""  PC
 SG_ S2P_Cfg7_CSCTempsNum_42 : 12|6@1+ (1,0) [0|63] ""  PC
 SG_ S2P_Cfg7_CSCCellTempsNum_42 : 18|6@1+ (1,0) [0|63] ""  PC

BO_ 2416504427 S2P_Cfg7__43: 8 SBMU
 SG_ S2P_Cfg7_CSCCellSeries_Num_43 : 0|8@1+ (1,0) [0|255] ""  PC
 SG_ S2P_Cfg7_CSCCellParal_Num_43 : 8|4@1+ (1,0) [0|15] ""  PC
 SG_ S2P_Cfg7_CSCTempsNum_43 : 12|6@1+ (1,0) [0|63] ""  PC
 SG_ S2P_Cfg7_CSCCellTempsNum_43 : 18|6@1+ (1,0) [0|63] ""  PC

BO_ 2416504428 S2P_Cfg7__44: 8 SBMU
 SG_ S2P_Cfg7_CSCCellSeries_Num_44 : 0|8@1+ (1,0) [0|255] ""  PC
 SG_ S2P_Cfg7_CSCCellParal_Num_44 : 8|4@1+ (1,0) [0|15] ""  PC
 SG_ S2P_Cfg7_CSCTempsNum_44 : 12|6@1+ (1,0) [0|63] ""  PC
 SG_ S2P_Cfg7_CSCCellTempsNum_44 : 18|6@1+ (1,0) [0|63] ""  PC

BO_ 2416504429 S2P_Cfg7__45: 8 SBMU
 SG_ S2P_Cfg7_CSCCellSeries_Num_45 : 0|8@1+ (1,0) [0|255] ""  PC
 SG_ S2P_Cfg7_CSCCellParal_Num_45 : 8|4@1+ (1,0) [0|15] ""  PC
 SG_ S2P_Cfg7_CSCTempsNum_45 : 12|6@1+ (1,0) [0|63] ""  PC
 SG_ S2P_Cfg7_CSCCellTempsNum_45 : 18|6@1+ (1,0) [0|63] ""  PC

BO_ 2416504430 S2P_Cfg7__46: 8 SBMU
 SG_ S2P_Cfg7_CSCCellSeries_Num_46 : 0|8@1+ (1,0) [0|255] ""  PC
 SG_ S2P_Cfg7_CSCCellParal_Num_46 : 8|4@1+ (1,0) [0|15] ""  PC
 SG_ S2P_Cfg7_CSCTempsNum_46 : 12|6@1+ (1,0) [0|63] ""  PC
 SG_ S2P_Cfg7_CSCCellTempsNum_46 : 18|6@1+ (1,0) [0|63] ""  PC

BO_ 2416504431 S2P_Cfg7__47: 8 SBMU
 SG_ S2P_Cfg7_CSCCellSeries_Num_47 : 0|8@1+ (1,0) [0|255] ""  PC
 SG_ S2P_Cfg7_CSCCellParal_Num_47 : 8|4@1+ (1,0) [0|15] ""  PC
 SG_ S2P_Cfg7_CSCTempsNum_47 : 12|6@1+ (1,0) [0|63] ""  PC
 SG_ S2P_Cfg7_CSCCellTempsNum_47 : 18|6@1+ (1,0) [0|63] ""  PC

BO_ 2416504432 S2P_Cfg7__48: 8 SBMU
 SG_ S2P_Cfg7_CSCCellSeries_Num_48 : 0|8@1+ (1,0) [0|255] ""  PC
 SG_ S2P_Cfg7_CSCCellParal_Num_48 : 8|4@1+ (1,0) [0|15] ""  PC
 SG_ S2P_Cfg7_CSCTempsNum_48 : 12|6@1+ (1,0) [0|63] ""  PC
 SG_ S2P_Cfg7_CSCCellTempsNum_48 : 18|6@1+ (1,0) [0|63] ""  PC

BO_ 2416504433 S2P_Cfg7__49: 8 SBMU
 SG_ S2P_Cfg7_CSCCellSeries_Num_49 : 0|8@1+ (1,0) [0|255] ""  PC
 SG_ S2P_Cfg7_CSCCellParal_Num_49 : 8|4@1+ (1,0) [0|15] ""  PC
 SG_ S2P_Cfg7_CSCTempsNum_49 : 12|6@1+ (1,0) [0|63] ""  PC
 SG_ S2P_Cfg7_CSCCellTempsNum_49 : 18|6@1+ (1,0) [0|63] ""  PC

BO_ 2416504434 S2P_Cfg7__50: 8 SBMU
 SG_ S2P_Cfg7_CSCCellSeries_Num_50 : 0|8@1+ (1,0) [0|255] ""  PC
 SG_ S2P_Cfg7_CSCCellParal_Num_50 : 8|4@1+ (1,0) [0|15] ""  PC
 SG_ S2P_Cfg7_CSCTempsNum_50 : 12|6@1+ (1,0) [0|63] ""  PC
 SG_ S2P_Cfg7_CSCCellTempsNum_50 : 18|6@1+ (1,0) [0|63] ""  PC

BO_ 2416504435 S2P_Cfg7__51: 8 SBMU
 SG_ S2P_Cfg7_CSCCellSeries_Num_51 : 0|8@1+ (1,0) [0|255] ""  PC
 SG_ S2P_Cfg7_CSCCellParal_Num_51 : 8|4@1+ (1,0) [0|15] ""  PC
 SG_ S2P_Cfg7_CSCTempsNum_51 : 12|6@1+ (1,0) [0|63] ""  PC
 SG_ S2P_Cfg7_CSCCellTempsNum_51 : 18|6@1+ (1,0) [0|63] ""  PC

BO_ 2416504436 S2P_Cfg7__52: 8 SBMU
 SG_ S2P_Cfg7_CSCCellSeries_Num_52 : 0|8@1+ (1,0) [0|255] ""  PC
 SG_ S2P_Cfg7_CSCCellParal_Num_52 : 8|4@1+ (1,0) [0|15] ""  PC
 SG_ S2P_Cfg7_CSCTempsNum_52 : 12|6@1+ (1,0) [0|63] ""  PC
 SG_ S2P_Cfg7_CSCCellTempsNum_52 : 18|6@1+ (1,0) [0|63] ""  PC

BO_ 2416504437 S2P_Cfg7__53: 8 SBMU
 SG_ S2P_Cfg7_CSCCellSeries_Num_53 : 0|8@1+ (1,0) [0|255] ""  PC
 SG_ S2P_Cfg7_CSCCellParal_Num_53 : 8|4@1+ (1,0) [0|15] ""  PC
 SG_ S2P_Cfg7_CSCTempsNum_53 : 12|6@1+ (1,0) [0|63] ""  PC
 SG_ S2P_Cfg7_CSCCellTempsNum_53 : 18|6@1+ (1,0) [0|63] ""  PC

BO_ 2416504438 S2P_Cfg7__54: 8 SBMU
 SG_ S2P_Cfg7_CSCCellSeries_Num_54 : 0|8@1+ (1,0) [0|255] ""  PC
 SG_ S2P_Cfg7_CSCCellParal_Num_54 : 8|4@1+ (1,0) [0|15] ""  PC
 SG_ S2P_Cfg7_CSCTempsNum_54 : 12|6@1+ (1,0) [0|63] ""  PC
 SG_ S2P_Cfg7_CSCCellTempsNum_54 : 18|6@1+ (1,0) [0|63] ""  PC

BO_ 2416504439 S2P_Cfg7__55: 8 SBMU
 SG_ S2P_Cfg7_CSCCellSeries_Num_55 : 0|8@1+ (1,0) [0|255] ""  PC
 SG_ S2P_Cfg7_CSCCellParal_Num_55 : 8|4@1+ (1,0) [0|15] ""  PC
 SG_ S2P_Cfg7_CSCTempsNum_55 : 12|6@1+ (1,0) [0|63] ""  PC
 SG_ S2P_Cfg7_CSCCellTempsNum_55 : 18|6@1+ (1,0) [0|63] ""  PC

BO_ 2416504440 S2P_Cfg7__56: 8 SBMU
 SG_ S2P_Cfg7_CSCCellSeries_Num_56 : 0|8@1+ (1,0) [0|255] ""  PC
 SG_ S2P_Cfg7_CSCCellParal_Num_56 : 8|4@1+ (1,0) [0|15] ""  PC
 SG_ S2P_Cfg7_CSCTempsNum_56 : 12|6@1+ (1,0) [0|63] ""  PC
 SG_ S2P_Cfg7_CSCCellTempsNum_56 : 18|6@1+ (1,0) [0|63] ""  PC

BO_ 2416504441 S2P_Cfg7__57: 8 SBMU
 SG_ S2P_Cfg7_CSCCellSeries_Num_57 : 0|8@1+ (1,0) [0|255] ""  PC
 SG_ S2P_Cfg7_CSCCellParal_Num_57 : 8|4@1+ (1,0) [0|15] ""  PC
 SG_ S2P_Cfg7_CSCTempsNum_57 : 12|6@1+ (1,0) [0|63] ""  PC
 SG_ S2P_Cfg7_CSCCellTempsNum_57 : 18|6@1+ (1,0) [0|63] ""  PC

BO_ 2416504442 S2P_Cfg7__58: 8 SBMU
 SG_ S2P_Cfg7_CSCCellSeries_Num_58 : 0|8@1+ (1,0) [0|255] ""  PC
 SG_ S2P_Cfg7_CSCCellParal_Num_58 : 8|4@1+ (1,0) [0|15] ""  PC
 SG_ S2P_Cfg7_CSCTempsNum_58 : 12|6@1+ (1,0) [0|63] ""  PC
 SG_ S2P_Cfg7_CSCCellTempsNum_58 : 18|6@1+ (1,0) [0|63] ""  PC

BO_ 2416504443 S2P_Cfg7__59: 8 SBMU
 SG_ S2P_Cfg7_CSCCellSeries_Num_59 : 0|8@1+ (1,0) [0|255] ""  PC
 SG_ S2P_Cfg7_CSCCellParal_Num_59 : 8|4@1+ (1,0) [0|15] ""  PC
 SG_ S2P_Cfg7_CSCTempsNum_59 : 12|6@1+ (1,0) [0|63] ""  PC
 SG_ S2P_Cfg7_CSCCellTempsNum_59 : 18|6@1+ (1,0) [0|63] ""  PC

BO_ 2416504444 S2P_Cfg7__60: 8 SBMU
 SG_ S2P_Cfg7_CSCCellSeries_Num_60 : 0|8@1+ (1,0) [0|255] ""  PC
 SG_ S2P_Cfg7_CSCCellParal_Num_60 : 8|4@1+ (1,0) [0|15] ""  PC
 SG_ S2P_Cfg7_CSCTempsNum_60 : 12|6@1+ (1,0) [0|63] ""  PC
 SG_ S2P_Cfg7_CSCCellTempsNum_60 : 18|6@1+ (1,0) [0|63] ""  PC

BO_ 2416504445 S2P_Cfg7__61: 8 SBMU
 SG_ S2P_Cfg7_CSCCellSeries_Num_61 : 0|8@1+ (1,0) [0|255] ""  PC
 SG_ S2P_Cfg7_CSCCellParal_Num_61 : 8|4@1+ (1,0) [0|15] ""  PC
 SG_ S2P_Cfg7_CSCTempsNum_61 : 12|6@1+ (1,0) [0|63] ""  PC
 SG_ S2P_Cfg7_CSCCellTempsNum_61 : 18|6@1+ (1,0) [0|63] ""  PC

BO_ 2416504446 S2P_Cfg7__62: 8 SBMU
 SG_ S2P_Cfg7_CSCCellSeries_Num_62 : 0|8@1+ (1,0) [0|255] ""  PC
 SG_ S2P_Cfg7_CSCCellParal_Num_62 : 8|4@1+ (1,0) [0|15] ""  PC
 SG_ S2P_Cfg7_CSCTempsNum_62 : 12|6@1+ (1,0) [0|63] ""  PC
 SG_ S2P_Cfg7_CSCCellTempsNum_62 : 18|6@1+ (1,0) [0|63] ""  PC

BO_ 2416504447 S2P_Cfg7__63: 8 SBMU
 SG_ S2P_Cfg7_CSCCellSeries_Num_63 : 0|8@1+ (1,0) [0|255] ""  PC
 SG_ S2P_Cfg7_CSCCellParal_Num_63 : 8|4@1+ (1,0) [0|15] ""  PC
 SG_ S2P_Cfg7_CSCTempsNum_63 : 12|6@1+ (1,0) [0|63] ""  PC
 SG_ S2P_Cfg7_CSCCellTempsNum_63 : 18|6@1+ (1,0) [0|63] ""  PC

BO_ 2417552961 S2P_Cfg8__01: 8 SBMU
 SG_ S2P_Cfg8_SW_Ver_Byte1_01 : 0|8@1+ (1,0) [0|255] ""  PC
 SG_ S2P_Cfg8_SW_Ver_Byte2_01 : 8|8@1+ (1,0) [0|255] ""  PC
 SG_ S2P_Cfg8_SW_Ver_Byte3_01 : 16|8@1+ (1,0) [0|255] ""  PC
 SG_ S2P_Cfg8_SW_Ver_Byte4_01 : 24|8@1+ (1,0) [0|255] ""  PC
 SG_ S2P_Cfg8_SW_Ver_Byte5_01 : 32|8@1+ (1,0) [0|255] ""  PC
 SG_ S2P_Cfg8_SW_Ver_Byte6_01 : 40|8@1+ (1,0) [0|255] ""  PC
 SG_ S2P_Cfg8_SW_Ver_Byte7_01 : 48|8@1+ (1,0) [0|255] ""  PC
 SG_ S2P_Cfg8_SW_Ver_Byte8_01 : 56|8@1+ (1,0) [0|255] ""  PC

BO_ 2417552962 S2P_Cfg8__02: 8 SBMU
 SG_ S2P_Cfg8_SW_Ver_Byte1_02 : 0|8@1+ (1,0) [0|255] ""  PC
 SG_ S2P_Cfg8_SW_Ver_Byte2_02 : 8|8@1+ (1,0) [0|255] ""  PC
 SG_ S2P_Cfg8_SW_Ver_Byte3_02 : 16|8@1+ (1,0) [0|255] ""  PC
 SG_ S2P_Cfg8_SW_Ver_Byte4_02 : 24|8@1+ (1,0) [0|255] ""  PC
 SG_ S2P_Cfg8_SW_Ver_Byte5_02 : 32|8@1+ (1,0) [0|255] ""  PC
 SG_ S2P_Cfg8_SW_Ver_Byte6_02 : 40|8@1+ (1,0) [0|255] ""  PC
 SG_ S2P_Cfg8_SW_Ver_Byte7_02 : 48|8@1+ (1,0) [0|255] ""  PC
 SG_ S2P_Cfg8_SW_Ver_Byte8_02 : 56|8@1+ (1,0) [0|255] ""  PC

BO_ 2417552963 S2P_Cfg8__03: 8 SBMU
 SG_ S2P_Cfg8_SW_Ver_Byte1_03 : 0|8@1+ (1,0) [0|255] ""  PC
 SG_ S2P_Cfg8_SW_Ver_Byte2_03 : 8|8@1+ (1,0) [0|255] ""  PC
 SG_ S2P_Cfg8_SW_Ver_Byte3_03 : 16|8@1+ (1,0) [0|255] ""  PC
 SG_ S2P_Cfg8_SW_Ver_Byte4_03 : 24|8@1+ (1,0) [0|255] ""  PC
 SG_ S2P_Cfg8_SW_Ver_Byte5_03 : 32|8@1+ (1,0) [0|255] ""  PC
 SG_ S2P_Cfg8_SW_Ver_Byte6_03 : 40|8@1+ (1,0) [0|255] ""  PC
 SG_ S2P_Cfg8_SW_Ver_Byte7_03 : 48|8@1+ (1,0) [0|255] ""  PC
 SG_ S2P_Cfg8_SW_Ver_Byte8_03 : 56|8@1+ (1,0) [0|255] ""  PC

BO_ 2417552964 S2P_Cfg8__04: 8 SBMU
 SG_ S2P_Cfg8_SW_Ver_Byte1_04 : 0|8@1+ (1,0) [0|255] ""  PC
 SG_ S2P_Cfg8_SW_Ver_Byte2_04 : 8|8@1+ (1,0) [0|255] ""  PC
 SG_ S2P_Cfg8_SW_Ver_Byte3_04 : 16|8@1+ (1,0) [0|255] ""  PC
 SG_ S2P_Cfg8_SW_Ver_Byte4_04 : 24|8@1+ (1,0) [0|255] ""  PC
 SG_ S2P_Cfg8_SW_Ver_Byte5_04 : 32|8@1+ (1,0) [0|255] ""  PC
 SG_ S2P_Cfg8_SW_Ver_Byte6_04 : 40|8@1+ (1,0) [0|255] ""  PC
 SG_ S2P_Cfg8_SW_Ver_Byte7_04 : 48|8@1+ (1,0) [0|255] ""  PC
 SG_ S2P_Cfg8_SW_Ver_Byte8_04 : 56|8@1+ (1,0) [0|255] ""  PC

BO_ 2417552965 S2P_Cfg8__05: 8 SBMU
 SG_ S2P_Cfg8_SW_Ver_Byte1_05 : 0|8@1+ (1,0) [0|255] ""  PC
 SG_ S2P_Cfg8_SW_Ver_Byte2_05 : 8|8@1+ (1,0) [0|255] ""  PC
 SG_ S2P_Cfg8_SW_Ver_Byte3_05 : 16|8@1+ (1,0) [0|255] ""  PC
 SG_ S2P_Cfg8_SW_Ver_Byte4_05 : 24|8@1+ (1,0) [0|255] ""  PC
 SG_ S2P_Cfg8_SW_Ver_Byte5_05 : 32|8@1+ (1,0) [0|255] ""  PC
 SG_ S2P_Cfg8_SW_Ver_Byte6_05 : 40|8@1+ (1,0) [0|255] ""  PC
 SG_ S2P_Cfg8_SW_Ver_Byte7_05 : 48|8@1+ (1,0) [0|255] ""  PC
 SG_ S2P_Cfg8_SW_Ver_Byte8_05 : 56|8@1+ (1,0) [0|255] ""  PC

BO_ 2417552966 S2P_Cfg8__06: 8 SBMU
 SG_ S2P_Cfg8_SW_Ver_Byte1_06 : 0|8@1+ (1,0) [0|255] ""  PC
 SG_ S2P_Cfg8_SW_Ver_Byte2_06 : 8|8@1+ (1,0) [0|255] ""  PC
 SG_ S2P_Cfg8_SW_Ver_Byte3_06 : 16|8@1+ (1,0) [0|255] ""  PC
 SG_ S2P_Cfg8_SW_Ver_Byte4_06 : 24|8@1+ (1,0) [0|255] ""  PC
 SG_ S2P_Cfg8_SW_Ver_Byte5_06 : 32|8@1+ (1,0) [0|255] ""  PC
 SG_ S2P_Cfg8_SW_Ver_Byte6_06 : 40|8@1+ (1,0) [0|255] ""  PC
 SG_ S2P_Cfg8_SW_Ver_Byte7_06 : 48|8@1+ (1,0) [0|255] ""  PC
 SG_ S2P_Cfg8_SW_Ver_Byte8_06 : 56|8@1+ (1,0) [0|255] ""  PC

BO_ 2417552967 S2P_Cfg8__07: 8 SBMU
 SG_ S2P_Cfg8_SW_Ver_Byte1_07 : 0|8@1+ (1,0) [0|255] ""  PC
 SG_ S2P_Cfg8_SW_Ver_Byte2_07 : 8|8@1+ (1,0) [0|255] ""  PC
 SG_ S2P_Cfg8_SW_Ver_Byte3_07 : 16|8@1+ (1,0) [0|255] ""  PC
 SG_ S2P_Cfg8_SW_Ver_Byte4_07 : 24|8@1+ (1,0) [0|255] ""  PC
 SG_ S2P_Cfg8_SW_Ver_Byte5_07 : 32|8@1+ (1,0) [0|255] ""  PC
 SG_ S2P_Cfg8_SW_Ver_Byte6_07 : 40|8@1+ (1,0) [0|255] ""  PC
 SG_ S2P_Cfg8_SW_Ver_Byte7_07 : 48|8@1+ (1,0) [0|255] ""  PC
 SG_ S2P_Cfg8_SW_Ver_Byte8_07 : 56|8@1+ (1,0) [0|255] ""  PC

BO_ 2417552968 S2P_Cfg8__08: 8 SBMU
 SG_ S2P_Cfg8_SW_Ver_Byte1_08 : 0|8@1+ (1,0) [0|255] ""  PC
 SG_ S2P_Cfg8_SW_Ver_Byte2_08 : 8|8@1+ (1,0) [0|255] ""  PC
 SG_ S2P_Cfg8_SW_Ver_Byte3_08 : 16|8@1+ (1,0) [0|255] ""  PC
 SG_ S2P_Cfg8_SW_Ver_Byte4_08 : 24|8@1+ (1,0) [0|255] ""  PC
 SG_ S2P_Cfg8_SW_Ver_Byte5_08 : 32|8@1+ (1,0) [0|255] ""  PC
 SG_ S2P_Cfg8_SW_Ver_Byte6_08 : 40|8@1+ (1,0) [0|255] ""  PC
 SG_ S2P_Cfg8_SW_Ver_Byte7_08 : 48|8@1+ (1,0) [0|255] ""  PC
 SG_ S2P_Cfg8_SW_Ver_Byte8_08 : 56|8@1+ (1,0) [0|255] ""  PC

BO_ 2417552969 S2P_Cfg8__09: 8 SBMU
 SG_ S2P_Cfg8_SW_Ver_Byte1_09 : 0|8@1+ (1,0) [0|255] ""  PC
 SG_ S2P_Cfg8_SW_Ver_Byte2_09 : 8|8@1+ (1,0) [0|255] ""  PC
 SG_ S2P_Cfg8_SW_Ver_Byte3_09 : 16|8@1+ (1,0) [0|255] ""  PC
 SG_ S2P_Cfg8_SW_Ver_Byte4_09 : 24|8@1+ (1,0) [0|255] ""  PC
 SG_ S2P_Cfg8_SW_Ver_Byte5_09 : 32|8@1+ (1,0) [0|255] ""  PC
 SG_ S2P_Cfg8_SW_Ver_Byte6_09 : 40|8@1+ (1,0) [0|255] ""  PC
 SG_ S2P_Cfg8_SW_Ver_Byte7_09 : 48|8@1+ (1,0) [0|255] ""  PC
 SG_ S2P_Cfg8_SW_Ver_Byte8_09 : 56|8@1+ (1,0) [0|255] ""  PC

BO_ 2417552970 S2P_Cfg8__10: 8 SBMU
 SG_ S2P_Cfg8_SW_Ver_Byte1_10 : 0|8@1+ (1,0) [0|255] ""  PC
 SG_ S2P_Cfg8_SW_Ver_Byte2_10 : 8|8@1+ (1,0) [0|255] ""  PC
 SG_ S2P_Cfg8_SW_Ver_Byte3_10 : 16|8@1+ (1,0) [0|255] ""  PC
 SG_ S2P_Cfg8_SW_Ver_Byte4_10 : 24|8@1+ (1,0) [0|255] ""  PC
 SG_ S2P_Cfg8_SW_Ver_Byte5_10 : 32|8@1+ (1,0) [0|255] ""  PC
 SG_ S2P_Cfg8_SW_Ver_Byte6_10 : 40|8@1+ (1,0) [0|255] ""  PC
 SG_ S2P_Cfg8_SW_Ver_Byte7_10 : 48|8@1+ (1,0) [0|255] ""  PC
 SG_ S2P_Cfg8_SW_Ver_Byte8_10 : 56|8@1+ (1,0) [0|255] ""  PC

BO_ 2417552971 S2P_Cfg8__11: 8 SBMU
 SG_ S2P_Cfg8_SW_Ver_Byte1_11 : 0|8@1+ (1,0) [0|255] ""  PC
 SG_ S2P_Cfg8_SW_Ver_Byte2_11 : 8|8@1+ (1,0) [0|255] ""  PC
 SG_ S2P_Cfg8_SW_Ver_Byte3_11 : 16|8@1+ (1,0) [0|255] ""  PC
 SG_ S2P_Cfg8_SW_Ver_Byte4_11 : 24|8@1+ (1,0) [0|255] ""  PC
 SG_ S2P_Cfg8_SW_Ver_Byte5_11 : 32|8@1+ (1,0) [0|255] ""  PC
 SG_ S2P_Cfg8_SW_Ver_Byte6_11 : 40|8@1+ (1,0) [0|255] ""  PC
 SG_ S2P_Cfg8_SW_Ver_Byte7_11 : 48|8@1+ (1,0) [0|255] ""  PC
 SG_ S2P_Cfg8_SW_Ver_Byte8_11 : 56|8@1+ (1,0) [0|255] ""  PC

BO_ 2417552972 S2P_Cfg8__12: 8 SBMU
 SG_ S2P_Cfg8_SW_Ver_Byte1_12 : 0|8@1+ (1,0) [0|255] ""  PC
 SG_ S2P_Cfg8_SW_Ver_Byte2_12 : 8|8@1+ (1,0) [0|255] ""  PC
 SG_ S2P_Cfg8_SW_Ver_Byte3_12 : 16|8@1+ (1,0) [0|255] ""  PC
 SG_ S2P_Cfg8_SW_Ver_Byte4_12 : 24|8@1+ (1,0) [0|255] ""  PC
 SG_ S2P_Cfg8_SW_Ver_Byte5_12 : 32|8@1+ (1,0) [0|255] ""  PC
 SG_ S2P_Cfg8_SW_Ver_Byte6_12 : 40|8@1+ (1,0) [0|255] ""  PC
 SG_ S2P_Cfg8_SW_Ver_Byte7_12 : 48|8@1+ (1,0) [0|255] ""  PC
 SG_ S2P_Cfg8_SW_Ver_Byte8_12 : 56|8@1+ (1,0) [0|255] ""  PC

BO_ 2417552973 S2P_Cfg8__13: 8 SBMU
 SG_ S2P_Cfg8_SW_Ver_Byte1_13 : 0|8@1+ (1,0) [0|255] ""  PC
 SG_ S2P_Cfg8_SW_Ver_Byte2_13 : 8|8@1+ (1,0) [0|255] ""  PC
 SG_ S2P_Cfg8_SW_Ver_Byte3_13 : 16|8@1+ (1,0) [0|255] ""  PC
 SG_ S2P_Cfg8_SW_Ver_Byte4_13 : 24|8@1+ (1,0) [0|255] ""  PC
 SG_ S2P_Cfg8_SW_Ver_Byte5_13 : 32|8@1+ (1,0) [0|255] ""  PC
 SG_ S2P_Cfg8_SW_Ver_Byte6_13 : 40|8@1+ (1,0) [0|255] ""  PC
 SG_ S2P_Cfg8_SW_Ver_Byte7_13 : 48|8@1+ (1,0) [0|255] ""  PC
 SG_ S2P_Cfg8_SW_Ver_Byte8_13 : 56|8@1+ (1,0) [0|255] ""  PC

BO_ 2417552974 S2P_Cfg8__14: 8 SBMU
 SG_ S2P_Cfg8_SW_Ver_Byte1_14 : 0|8@1+ (1,0) [0|255] ""  PC
 SG_ S2P_Cfg8_SW_Ver_Byte2_14 : 8|8@1+ (1,0) [0|255] ""  PC
 SG_ S2P_Cfg8_SW_Ver_Byte3_14 : 16|8@1+ (1,0) [0|255] ""  PC
 SG_ S2P_Cfg8_SW_Ver_Byte4_14 : 24|8@1+ (1,0) [0|255] ""  PC
 SG_ S2P_Cfg8_SW_Ver_Byte5_14 : 32|8@1+ (1,0) [0|255] ""  PC
 SG_ S2P_Cfg8_SW_Ver_Byte6_14 : 40|8@1+ (1,0) [0|255] ""  PC
 SG_ S2P_Cfg8_SW_Ver_Byte7_14 : 48|8@1+ (1,0) [0|255] ""  PC
 SG_ S2P_Cfg8_SW_Ver_Byte8_14 : 56|8@1+ (1,0) [0|255] ""  PC

BO_ 2417552975 S2P_Cfg8__15: 8 SBMU
 SG_ S2P_Cfg8_SW_Ver_Byte1_15 : 0|8@1+ (1,0) [0|255] ""  PC
 SG_ S2P_Cfg8_SW_Ver_Byte2_15 : 8|8@1+ (1,0) [0|255] ""  PC
 SG_ S2P_Cfg8_SW_Ver_Byte3_15 : 16|8@1+ (1,0) [0|255] ""  PC
 SG_ S2P_Cfg8_SW_Ver_Byte4_15 : 24|8@1+ (1,0) [0|255] ""  PC
 SG_ S2P_Cfg8_SW_Ver_Byte5_15 : 32|8@1+ (1,0) [0|255] ""  PC
 SG_ S2P_Cfg8_SW_Ver_Byte6_15 : 40|8@1+ (1,0) [0|255] ""  PC
 SG_ S2P_Cfg8_SW_Ver_Byte7_15 : 48|8@1+ (1,0) [0|255] ""  PC
 SG_ S2P_Cfg8_SW_Ver_Byte8_15 : 56|8@1+ (1,0) [0|255] ""  PC

BO_ 2417552976 S2P_Cfg8__16: 8 SBMU
 SG_ S2P_Cfg8_SW_Ver_Byte1_16 : 0|8@1+ (1,0) [0|255] ""  PC
 SG_ S2P_Cfg8_SW_Ver_Byte2_16 : 8|8@1+ (1,0) [0|255] ""  PC
 SG_ S2P_Cfg8_SW_Ver_Byte3_16 : 16|8@1+ (1,0) [0|255] ""  PC
 SG_ S2P_Cfg8_SW_Ver_Byte4_16 : 24|8@1+ (1,0) [0|255] ""  PC
 SG_ S2P_Cfg8_SW_Ver_Byte5_16 : 32|8@1+ (1,0) [0|255] ""  PC
 SG_ S2P_Cfg8_SW_Ver_Byte6_16 : 40|8@1+ (1,0) [0|255] ""  PC
 SG_ S2P_Cfg8_SW_Ver_Byte7_16 : 48|8@1+ (1,0) [0|255] ""  PC
 SG_ S2P_Cfg8_SW_Ver_Byte8_16 : 56|8@1+ (1,0) [0|255] ""  PC

BO_ 2417552977 S2P_Cfg8__17: 8 SBMU
 SG_ S2P_Cfg8_SW_Ver_Byte1_17 : 0|8@1+ (1,0) [0|255] ""  PC
 SG_ S2P_Cfg8_SW_Ver_Byte2_17 : 8|8@1+ (1,0) [0|255] ""  PC
 SG_ S2P_Cfg8_SW_Ver_Byte3_17 : 16|8@1+ (1,0) [0|255] ""  PC
 SG_ S2P_Cfg8_SW_Ver_Byte4_17 : 24|8@1+ (1,0) [0|255] ""  PC
 SG_ S2P_Cfg8_SW_Ver_Byte5_17 : 32|8@1+ (1,0) [0|255] ""  PC
 SG_ S2P_Cfg8_SW_Ver_Byte6_17 : 40|8@1+ (1,0) [0|255] ""  PC
 SG_ S2P_Cfg8_SW_Ver_Byte7_17 : 48|8@1+ (1,0) [0|255] ""  PC
 SG_ S2P_Cfg8_SW_Ver_Byte8_17 : 56|8@1+ (1,0) [0|255] ""  PC

BO_ 2417552978 S2P_Cfg8__18: 8 SBMU
 SG_ S2P_Cfg8_SW_Ver_Byte1_18 : 0|8@1+ (1,0) [0|255] ""  PC
 SG_ S2P_Cfg8_SW_Ver_Byte2_18 : 8|8@1+ (1,0) [0|255] ""  PC
 SG_ S2P_Cfg8_SW_Ver_Byte3_18 : 16|8@1+ (1,0) [0|255] ""  PC
 SG_ S2P_Cfg8_SW_Ver_Byte4_18 : 24|8@1+ (1,0) [0|255] ""  PC
 SG_ S2P_Cfg8_SW_Ver_Byte5_18 : 32|8@1+ (1,0) [0|255] ""  PC
 SG_ S2P_Cfg8_SW_Ver_Byte6_18 : 40|8@1+ (1,0) [0|255] ""  PC
 SG_ S2P_Cfg8_SW_Ver_Byte7_18 : 48|8@1+ (1,0) [0|255] ""  PC
 SG_ S2P_Cfg8_SW_Ver_Byte8_18 : 56|8@1+ (1,0) [0|255] ""  PC

BO_ 2417552979 S2P_Cfg8__19: 8 SBMU
 SG_ S2P_Cfg8_SW_Ver_Byte1_19 : 0|8@1+ (1,0) [0|255] ""  PC
 SG_ S2P_Cfg8_SW_Ver_Byte2_19 : 8|8@1+ (1,0) [0|255] ""  PC
 SG_ S2P_Cfg8_SW_Ver_Byte3_19 : 16|8@1+ (1,0) [0|255] ""  PC
 SG_ S2P_Cfg8_SW_Ver_Byte4_19 : 24|8@1+ (1,0) [0|255] ""  PC
 SG_ S2P_Cfg8_SW_Ver_Byte5_19 : 32|8@1+ (1,0) [0|255] ""  PC
 SG_ S2P_Cfg8_SW_Ver_Byte6_19 : 40|8@1+ (1,0) [0|255] ""  PC
 SG_ S2P_Cfg8_SW_Ver_Byte7_19 : 48|8@1+ (1,0) [0|255] ""  PC
 SG_ S2P_Cfg8_SW_Ver_Byte8_19 : 56|8@1+ (1,0) [0|255] ""  PC

BO_ 2417552980 S2P_Cfg8__20: 8 SBMU
 SG_ S2P_Cfg8_SW_Ver_Byte1_20 : 0|8@1+ (1,0) [0|255] ""  PC
 SG_ S2P_Cfg8_SW_Ver_Byte2_20 : 8|8@1+ (1,0) [0|255] ""  PC
 SG_ S2P_Cfg8_SW_Ver_Byte3_20 : 16|8@1+ (1,0) [0|255] ""  PC
 SG_ S2P_Cfg8_SW_Ver_Byte4_20 : 24|8@1+ (1,0) [0|255] ""  PC
 SG_ S2P_Cfg8_SW_Ver_Byte5_20 : 32|8@1+ (1,0) [0|255] ""  PC
 SG_ S2P_Cfg8_SW_Ver_Byte6_20 : 40|8@1+ (1,0) [0|255] ""  PC
 SG_ S2P_Cfg8_SW_Ver_Byte7_20 : 48|8@1+ (1,0) [0|255] ""  PC
 SG_ S2P_Cfg8_SW_Ver_Byte8_20 : 56|8@1+ (1,0) [0|255] ""  PC

BO_ 2417552981 S2P_Cfg8__21: 8 SBMU
 SG_ S2P_Cfg8_SW_Ver_Byte1_21 : 0|8@1+ (1,0) [0|255] ""  PC
 SG_ S2P_Cfg8_SW_Ver_Byte2_21 : 8|8@1+ (1,0) [0|255] ""  PC
 SG_ S2P_Cfg8_SW_Ver_Byte3_21 : 16|8@1+ (1,0) [0|255] ""  PC
 SG_ S2P_Cfg8_SW_Ver_Byte4_21 : 24|8@1+ (1,0) [0|255] ""  PC
 SG_ S2P_Cfg8_SW_Ver_Byte5_21 : 32|8@1+ (1,0) [0|255] ""  PC
 SG_ S2P_Cfg8_SW_Ver_Byte6_21 : 40|8@1+ (1,0) [0|255] ""  PC
 SG_ S2P_Cfg8_SW_Ver_Byte7_21 : 48|8@1+ (1,0) [0|255] ""  PC
 SG_ S2P_Cfg8_SW_Ver_Byte8_21 : 56|8@1+ (1,0) [0|255] ""  PC

BO_ 2417552982 S2P_Cfg8__22: 8 SBMU
 SG_ S2P_Cfg8_SW_Ver_Byte1_22 : 0|8@1+ (1,0) [0|255] ""  PC
 SG_ S2P_Cfg8_SW_Ver_Byte2_22 : 8|8@1+ (1,0) [0|255] ""  PC
 SG_ S2P_Cfg8_SW_Ver_Byte3_22 : 16|8@1+ (1,0) [0|255] ""  PC
 SG_ S2P_Cfg8_SW_Ver_Byte4_22 : 24|8@1+ (1,0) [0|255] ""  PC
 SG_ S2P_Cfg8_SW_Ver_Byte5_22 : 32|8@1+ (1,0) [0|255] ""  PC
 SG_ S2P_Cfg8_SW_Ver_Byte6_22 : 40|8@1+ (1,0) [0|255] ""  PC
 SG_ S2P_Cfg8_SW_Ver_Byte7_22 : 48|8@1+ (1,0) [0|255] ""  PC
 SG_ S2P_Cfg8_SW_Ver_Byte8_22 : 56|8@1+ (1,0) [0|255] ""  PC

BO_ 2417552983 S2P_Cfg8__23: 8 SBMU
 SG_ S2P_Cfg8_SW_Ver_Byte1_23 : 0|8@1+ (1,0) [0|255] ""  PC
 SG_ S2P_Cfg8_SW_Ver_Byte2_23 : 8|8@1+ (1,0) [0|255] ""  PC
 SG_ S2P_Cfg8_SW_Ver_Byte3_23 : 16|8@1+ (1,0) [0|255] ""  PC
 SG_ S2P_Cfg8_SW_Ver_Byte4_23 : 24|8@1+ (1,0) [0|255] ""  PC
 SG_ S2P_Cfg8_SW_Ver_Byte5_23 : 32|8@1+ (1,0) [0|255] ""  PC
 SG_ S2P_Cfg8_SW_Ver_Byte6_23 : 40|8@1+ (1,0) [0|255] ""  PC
 SG_ S2P_Cfg8_SW_Ver_Byte7_23 : 48|8@1+ (1,0) [0|255] ""  PC
 SG_ S2P_Cfg8_SW_Ver_Byte8_23 : 56|8@1+ (1,0) [0|255] ""  PC

BO_ 2417552984 S2P_Cfg8__24: 8 SBMU
 SG_ S2P_Cfg8_SW_Ver_Byte1_24 : 0|8@1+ (1,0) [0|255] ""  PC
 SG_ S2P_Cfg8_SW_Ver_Byte2_24 : 8|8@1+ (1,0) [0|255] ""  PC
 SG_ S2P_Cfg8_SW_Ver_Byte3_24 : 16|8@1+ (1,0) [0|255] ""  PC
 SG_ S2P_Cfg8_SW_Ver_Byte4_24 : 24|8@1+ (1,0) [0|255] ""  PC
 SG_ S2P_Cfg8_SW_Ver_Byte5_24 : 32|8@1+ (1,0) [0|255] ""  PC
 SG_ S2P_Cfg8_SW_Ver_Byte6_24 : 40|8@1+ (1,0) [0|255] ""  PC
 SG_ S2P_Cfg8_SW_Ver_Byte7_24 : 48|8@1+ (1,0) [0|255] ""  PC
 SG_ S2P_Cfg8_SW_Ver_Byte8_24 : 56|8@1+ (1,0) [0|255] ""  PC

BO_ 2417552985 S2P_Cfg8__25: 8 SBMU
 SG_ S2P_Cfg8_SW_Ver_Byte1_25 : 0|8@1+ (1,0) [0|255] ""  PC
 SG_ S2P_Cfg8_SW_Ver_Byte2_25 : 8|8@1+ (1,0) [0|255] ""  PC
 SG_ S2P_Cfg8_SW_Ver_Byte3_25 : 16|8@1+ (1,0) [0|255] ""  PC
 SG_ S2P_Cfg8_SW_Ver_Byte4_25 : 24|8@1+ (1,0) [0|255] ""  PC
 SG_ S2P_Cfg8_SW_Ver_Byte5_25 : 32|8@1+ (1,0) [0|255] ""  PC
 SG_ S2P_Cfg8_SW_Ver_Byte6_25 : 40|8@1+ (1,0) [0|255] ""  PC
 SG_ S2P_Cfg8_SW_Ver_Byte7_25 : 48|8@1+ (1,0) [0|255] ""  PC
 SG_ S2P_Cfg8_SW_Ver_Byte8_25 : 56|8@1+ (1,0) [0|255] ""  PC

BO_ 2417552986 S2P_Cfg8__26: 8 SBMU
 SG_ S2P_Cfg8_SW_Ver_Byte1_26 : 0|8@1+ (1,0) [0|255] ""  PC
 SG_ S2P_Cfg8_SW_Ver_Byte2_26 : 8|8@1+ (1,0) [0|255] ""  PC
 SG_ S2P_Cfg8_SW_Ver_Byte3_26 : 16|8@1+ (1,0) [0|255] ""  PC
 SG_ S2P_Cfg8_SW_Ver_Byte4_26 : 24|8@1+ (1,0) [0|255] ""  PC
 SG_ S2P_Cfg8_SW_Ver_Byte5_26 : 32|8@1+ (1,0) [0|255] ""  PC
 SG_ S2P_Cfg8_SW_Ver_Byte6_26 : 40|8@1+ (1,0) [0|255] ""  PC
 SG_ S2P_Cfg8_SW_Ver_Byte7_26 : 48|8@1+ (1,0) [0|255] ""  PC
 SG_ S2P_Cfg8_SW_Ver_Byte8_26 : 56|8@1+ (1,0) [0|255] ""  PC

BO_ 2417552987 S2P_Cfg8__27: 8 SBMU
 SG_ S2P_Cfg8_SW_Ver_Byte1_27 : 0|8@1+ (1,0) [0|255] ""  PC
 SG_ S2P_Cfg8_SW_Ver_Byte2_27 : 8|8@1+ (1,0) [0|255] ""  PC
 SG_ S2P_Cfg8_SW_Ver_Byte3_27 : 16|8@1+ (1,0) [0|255] ""  PC
 SG_ S2P_Cfg8_SW_Ver_Byte4_27 : 24|8@1+ (1,0) [0|255] ""  PC
 SG_ S2P_Cfg8_SW_Ver_Byte5_27 : 32|8@1+ (1,0) [0|255] ""  PC
 SG_ S2P_Cfg8_SW_Ver_Byte6_27 : 40|8@1+ (1,0) [0|255] ""  PC
 SG_ S2P_Cfg8_SW_Ver_Byte7_27 : 48|8@1+ (1,0) [0|255] ""  PC
 SG_ S2P_Cfg8_SW_Ver_Byte8_27 : 56|8@1+ (1,0) [0|255] ""  PC

BO_ 2417552988 S2P_Cfg8__28: 8 SBMU
 SG_ S2P_Cfg8_SW_Ver_Byte1_28 : 0|8@1+ (1,0) [0|255] ""  PC
 SG_ S2P_Cfg8_SW_Ver_Byte2_28 : 8|8@1+ (1,0) [0|255] ""  PC
 SG_ S2P_Cfg8_SW_Ver_Byte3_28 : 16|8@1+ (1,0) [0|255] ""  PC
 SG_ S2P_Cfg8_SW_Ver_Byte4_28 : 24|8@1+ (1,0) [0|255] ""  PC
 SG_ S2P_Cfg8_SW_Ver_Byte5_28 : 32|8@1+ (1,0) [0|255] ""  PC
 SG_ S2P_Cfg8_SW_Ver_Byte6_28 : 40|8@1+ (1,0) [0|255] ""  PC
 SG_ S2P_Cfg8_SW_Ver_Byte7_28 : 48|8@1+ (1,0) [0|255] ""  PC
 SG_ S2P_Cfg8_SW_Ver_Byte8_28 : 56|8@1+ (1,0) [0|255] ""  PC

BO_ 2417552989 S2P_Cfg8__29: 8 SBMU
 SG_ S2P_Cfg8_SW_Ver_Byte1_29 : 0|8@1+ (1,0) [0|255] ""  PC
 SG_ S2P_Cfg8_SW_Ver_Byte2_29 : 8|8@1+ (1,0) [0|255] ""  PC
 SG_ S2P_Cfg8_SW_Ver_Byte3_29 : 16|8@1+ (1,0) [0|255] ""  PC
 SG_ S2P_Cfg8_SW_Ver_Byte4_29 : 24|8@1+ (1,0) [0|255] ""  PC
 SG_ S2P_Cfg8_SW_Ver_Byte5_29 : 32|8@1+ (1,0) [0|255] ""  PC
 SG_ S2P_Cfg8_SW_Ver_Byte6_29 : 40|8@1+ (1,0) [0|255] ""  PC
 SG_ S2P_Cfg8_SW_Ver_Byte7_29 : 48|8@1+ (1,0) [0|255] ""  PC
 SG_ S2P_Cfg8_SW_Ver_Byte8_29 : 56|8@1+ (1,0) [0|255] ""  PC

BO_ 2417552990 S2P_Cfg8__30: 8 SBMU
 SG_ S2P_Cfg8_SW_Ver_Byte1_30 : 0|8@1+ (1,0) [0|255] ""  PC
 SG_ S2P_Cfg8_SW_Ver_Byte2_30 : 8|8@1+ (1,0) [0|255] ""  PC
 SG_ S2P_Cfg8_SW_Ver_Byte3_30 : 16|8@1+ (1,0) [0|255] ""  PC
 SG_ S2P_Cfg8_SW_Ver_Byte4_30 : 24|8@1+ (1,0) [0|255] ""  PC
 SG_ S2P_Cfg8_SW_Ver_Byte5_30 : 32|8@1+ (1,0) [0|255] ""  PC
 SG_ S2P_Cfg8_SW_Ver_Byte6_30 : 40|8@1+ (1,0) [0|255] ""  PC
 SG_ S2P_Cfg8_SW_Ver_Byte7_30 : 48|8@1+ (1,0) [0|255] ""  PC
 SG_ S2P_Cfg8_SW_Ver_Byte8_30 : 56|8@1+ (1,0) [0|255] ""  PC

BO_ 2417552991 S2P_Cfg8__31: 8 SBMU
 SG_ S2P_Cfg8_SW_Ver_Byte1_31 : 0|8@1+ (1,0) [0|255] ""  PC
 SG_ S2P_Cfg8_SW_Ver_Byte2_31 : 8|8@1+ (1,0) [0|255] ""  PC
 SG_ S2P_Cfg8_SW_Ver_Byte3_31 : 16|8@1+ (1,0) [0|255] ""  PC
 SG_ S2P_Cfg8_SW_Ver_Byte4_31 : 24|8@1+ (1,0) [0|255] ""  PC
 SG_ S2P_Cfg8_SW_Ver_Byte5_31 : 32|8@1+ (1,0) [0|255] ""  PC
 SG_ S2P_Cfg8_SW_Ver_Byte6_31 : 40|8@1+ (1,0) [0|255] ""  PC
 SG_ S2P_Cfg8_SW_Ver_Byte7_31 : 48|8@1+ (1,0) [0|255] ""  PC
 SG_ S2P_Cfg8_SW_Ver_Byte8_31 : 56|8@1+ (1,0) [0|255] ""  PC

BO_ 2417552992 S2P_Cfg8__32: 8 SBMU
 SG_ S2P_Cfg8_SW_Ver_Byte1_32 : 0|8@1+ (1,0) [0|255] ""  PC
 SG_ S2P_Cfg8_SW_Ver_Byte2_32 : 8|8@1+ (1,0) [0|255] ""  PC
 SG_ S2P_Cfg8_SW_Ver_Byte3_32 : 16|8@1+ (1,0) [0|255] ""  PC
 SG_ S2P_Cfg8_SW_Ver_Byte4_32 : 24|8@1+ (1,0) [0|255] ""  PC
 SG_ S2P_Cfg8_SW_Ver_Byte5_32 : 32|8@1+ (1,0) [0|255] ""  PC
 SG_ S2P_Cfg8_SW_Ver_Byte6_32 : 40|8@1+ (1,0) [0|255] ""  PC
 SG_ S2P_Cfg8_SW_Ver_Byte7_32 : 48|8@1+ (1,0) [0|255] ""  PC
 SG_ S2P_Cfg8_SW_Ver_Byte8_32 : 56|8@1+ (1,0) [0|255] ""  PC

BO_ 2417552993 S2P_Cfg8__33: 8 SBMU
 SG_ S2P_Cfg8_SW_Ver_Byte1_33 : 0|8@1+ (1,0) [0|255] ""  PC
 SG_ S2P_Cfg8_SW_Ver_Byte2_33 : 8|8@1+ (1,0) [0|255] ""  PC
 SG_ S2P_Cfg8_SW_Ver_Byte3_33 : 16|8@1+ (1,0) [0|255] ""  PC
 SG_ S2P_Cfg8_SW_Ver_Byte4_33 : 24|8@1+ (1,0) [0|255] ""  PC
 SG_ S2P_Cfg8_SW_Ver_Byte5_33 : 32|8@1+ (1,0) [0|255] ""  PC
 SG_ S2P_Cfg8_SW_Ver_Byte6_33 : 40|8@1+ (1,0) [0|255] ""  PC
 SG_ S2P_Cfg8_SW_Ver_Byte7_33 : 48|8@1+ (1,0) [0|255] ""  PC
 SG_ S2P_Cfg8_SW_Ver_Byte8_33 : 56|8@1+ (1,0) [0|255] ""  PC

BO_ 2417552994 S2P_Cfg8__34: 8 SBMU
 SG_ S2P_Cfg8_SW_Ver_Byte1_34 : 0|8@1+ (1,0) [0|255] ""  PC
 SG_ S2P_Cfg8_SW_Ver_Byte2_34 : 8|8@1+ (1,0) [0|255] ""  PC
 SG_ S2P_Cfg8_SW_Ver_Byte3_34 : 16|8@1+ (1,0) [0|255] ""  PC
 SG_ S2P_Cfg8_SW_Ver_Byte4_34 : 24|8@1+ (1,0) [0|255] ""  PC
 SG_ S2P_Cfg8_SW_Ver_Byte5_34 : 32|8@1+ (1,0) [0|255] ""  PC
 SG_ S2P_Cfg8_SW_Ver_Byte6_34 : 40|8@1+ (1,0) [0|255] ""  PC
 SG_ S2P_Cfg8_SW_Ver_Byte7_34 : 48|8@1+ (1,0) [0|255] ""  PC
 SG_ S2P_Cfg8_SW_Ver_Byte8_34 : 56|8@1+ (1,0) [0|255] ""  PC

BO_ 2417552995 S2P_Cfg8__35: 8 SBMU
 SG_ S2P_Cfg8_SW_Ver_Byte1_35 : 0|8@1+ (1,0) [0|255] ""  PC
 SG_ S2P_Cfg8_SW_Ver_Byte2_35 : 8|8@1+ (1,0) [0|255] ""  PC
 SG_ S2P_Cfg8_SW_Ver_Byte3_35 : 16|8@1+ (1,0) [0|255] ""  PC
 SG_ S2P_Cfg8_SW_Ver_Byte4_35 : 24|8@1+ (1,0) [0|255] ""  PC
 SG_ S2P_Cfg8_SW_Ver_Byte5_35 : 32|8@1+ (1,0) [0|255] ""  PC
 SG_ S2P_Cfg8_SW_Ver_Byte6_35 : 40|8@1+ (1,0) [0|255] ""  PC
 SG_ S2P_Cfg8_SW_Ver_Byte7_35 : 48|8@1+ (1,0) [0|255] ""  PC
 SG_ S2P_Cfg8_SW_Ver_Byte8_35 : 56|8@1+ (1,0) [0|255] ""  PC

BO_ 2417552996 S2P_Cfg8__36: 8 SBMU
 SG_ S2P_Cfg8_SW_Ver_Byte1_36 : 0|8@1+ (1,0) [0|255] ""  PC
 SG_ S2P_Cfg8_SW_Ver_Byte2_36 : 8|8@1+ (1,0) [0|255] ""  PC
 SG_ S2P_Cfg8_SW_Ver_Byte3_36 : 16|8@1+ (1,0) [0|255] ""  PC
 SG_ S2P_Cfg8_SW_Ver_Byte4_36 : 24|8@1+ (1,0) [0|255] ""  PC
 SG_ S2P_Cfg8_SW_Ver_Byte5_36 : 32|8@1+ (1,0) [0|255] ""  PC
 SG_ S2P_Cfg8_SW_Ver_Byte6_36 : 40|8@1+ (1,0) [0|255] ""  PC
 SG_ S2P_Cfg8_SW_Ver_Byte7_36 : 48|8@1+ (1,0) [0|255] ""  PC
 SG_ S2P_Cfg8_SW_Ver_Byte8_36 : 56|8@1+ (1,0) [0|255] ""  PC

BO_ 2417552997 S2P_Cfg8__37: 8 SBMU
 SG_ S2P_Cfg8_SW_Ver_Byte1_37 : 0|8@1+ (1,0) [0|255] ""  PC
 SG_ S2P_Cfg8_SW_Ver_Byte2_37 : 8|8@1+ (1,0) [0|255] ""  PC
 SG_ S2P_Cfg8_SW_Ver_Byte3_37 : 16|8@1+ (1,0) [0|255] ""  PC
 SG_ S2P_Cfg8_SW_Ver_Byte4_37 : 24|8@1+ (1,0) [0|255] ""  PC
 SG_ S2P_Cfg8_SW_Ver_Byte5_37 : 32|8@1+ (1,0) [0|255] ""  PC
 SG_ S2P_Cfg8_SW_Ver_Byte6_37 : 40|8@1+ (1,0) [0|255] ""  PC
 SG_ S2P_Cfg8_SW_Ver_Byte7_37 : 48|8@1+ (1,0) [0|255] ""  PC
 SG_ S2P_Cfg8_SW_Ver_Byte8_37 : 56|8@1+ (1,0) [0|255] ""  PC

BO_ 2417552998 S2P_Cfg8__38: 8 SBMU
 SG_ S2P_Cfg8_SW_Ver_Byte1_38 : 0|8@1+ (1,0) [0|255] ""  PC
 SG_ S2P_Cfg8_SW_Ver_Byte2_38 : 8|8@1+ (1,0) [0|255] ""  PC
 SG_ S2P_Cfg8_SW_Ver_Byte3_38 : 16|8@1+ (1,0) [0|255] ""  PC
 SG_ S2P_Cfg8_SW_Ver_Byte4_38 : 24|8@1+ (1,0) [0|255] ""  PC
 SG_ S2P_Cfg8_SW_Ver_Byte5_38 : 32|8@1+ (1,0) [0|255] ""  PC
 SG_ S2P_Cfg8_SW_Ver_Byte6_38 : 40|8@1+ (1,0) [0|255] ""  PC
 SG_ S2P_Cfg8_SW_Ver_Byte7_38 : 48|8@1+ (1,0) [0|255] ""  PC
 SG_ S2P_Cfg8_SW_Ver_Byte8_38 : 56|8@1+ (1,0) [0|255] ""  PC

BO_ 2417552999 S2P_Cfg8__39: 8 SBMU
 SG_ S2P_Cfg8_SW_Ver_Byte1_39 : 0|8@1+ (1,0) [0|255] ""  PC
 SG_ S2P_Cfg8_SW_Ver_Byte2_39 : 8|8@1+ (1,0) [0|255] ""  PC
 SG_ S2P_Cfg8_SW_Ver_Byte3_39 : 16|8@1+ (1,0) [0|255] ""  PC
 SG_ S2P_Cfg8_SW_Ver_Byte4_39 : 24|8@1+ (1,0) [0|255] ""  PC
 SG_ S2P_Cfg8_SW_Ver_Byte5_39 : 32|8@1+ (1,0) [0|255] ""  PC
 SG_ S2P_Cfg8_SW_Ver_Byte6_39 : 40|8@1+ (1,0) [0|255] ""  PC
 SG_ S2P_Cfg8_SW_Ver_Byte7_39 : 48|8@1+ (1,0) [0|255] ""  PC
 SG_ S2P_Cfg8_SW_Ver_Byte8_39 : 56|8@1+ (1,0) [0|255] ""  PC

BO_ 2417553000 S2P_Cfg8__40: 8 SBMU
 SG_ S2P_Cfg8_SW_Ver_Byte1_40 : 0|8@1+ (1,0) [0|255] ""  PC
 SG_ S2P_Cfg8_SW_Ver_Byte2_40 : 8|8@1+ (1,0) [0|255] ""  PC
 SG_ S2P_Cfg8_SW_Ver_Byte3_40 : 16|8@1+ (1,0) [0|255] ""  PC
 SG_ S2P_Cfg8_SW_Ver_Byte4_40 : 24|8@1+ (1,0) [0|255] ""  PC
 SG_ S2P_Cfg8_SW_Ver_Byte5_40 : 32|8@1+ (1,0) [0|255] ""  PC
 SG_ S2P_Cfg8_SW_Ver_Byte6_40 : 40|8@1+ (1,0) [0|255] ""  PC
 SG_ S2P_Cfg8_SW_Ver_Byte7_40 : 48|8@1+ (1,0) [0|255] ""  PC
 SG_ S2P_Cfg8_SW_Ver_Byte8_40 : 56|8@1+ (1,0) [0|255] ""  PC

BO_ 2417553001 S2P_Cfg8__41: 8 SBMU
 SG_ S2P_Cfg8_SW_Ver_Byte1_41 : 0|8@1+ (1,0) [0|255] ""  PC
 SG_ S2P_Cfg8_SW_Ver_Byte2_41 : 8|8@1+ (1,0) [0|255] ""  PC
 SG_ S2P_Cfg8_SW_Ver_Byte3_41 : 16|8@1+ (1,0) [0|255] ""  PC
 SG_ S2P_Cfg8_SW_Ver_Byte4_41 : 24|8@1+ (1,0) [0|255] ""  PC
 SG_ S2P_Cfg8_SW_Ver_Byte5_41 : 32|8@1+ (1,0) [0|255] ""  PC
 SG_ S2P_Cfg8_SW_Ver_Byte6_41 : 40|8@1+ (1,0) [0|255] ""  PC
 SG_ S2P_Cfg8_SW_Ver_Byte7_41 : 48|8@1+ (1,0) [0|255] ""  PC
 SG_ S2P_Cfg8_SW_Ver_Byte8_41 : 56|8@1+ (1,0) [0|255] ""  PC

BO_ 2417553002 S2P_Cfg8__42: 8 SBMU
 SG_ S2P_Cfg8_SW_Ver_Byte1_42 : 0|8@1+ (1,0) [0|255] ""  PC
 SG_ S2P_Cfg8_SW_Ver_Byte2_42 : 8|8@1+ (1,0) [0|255] ""  PC
 SG_ S2P_Cfg8_SW_Ver_Byte3_42 : 16|8@1+ (1,0) [0|255] ""  PC
 SG_ S2P_Cfg8_SW_Ver_Byte4_42 : 24|8@1+ (1,0) [0|255] ""  PC
 SG_ S2P_Cfg8_SW_Ver_Byte5_42 : 32|8@1+ (1,0) [0|255] ""  PC
 SG_ S2P_Cfg8_SW_Ver_Byte6_42 : 40|8@1+ (1,0) [0|255] ""  PC
 SG_ S2P_Cfg8_SW_Ver_Byte7_42 : 48|8@1+ (1,0) [0|255] ""  PC
 SG_ S2P_Cfg8_SW_Ver_Byte8_42 : 56|8@1+ (1,0) [0|255] ""  PC

BO_ 2417553003 S2P_Cfg8__43: 8 SBMU
 SG_ S2P_Cfg8_SW_Ver_Byte1_43 : 0|8@1+ (1,0) [0|255] ""  PC
 SG_ S2P_Cfg8_SW_Ver_Byte2_43 : 8|8@1+ (1,0) [0|255] ""  PC
 SG_ S2P_Cfg8_SW_Ver_Byte3_43 : 16|8@1+ (1,0) [0|255] ""  PC
 SG_ S2P_Cfg8_SW_Ver_Byte4_43 : 24|8@1+ (1,0) [0|255] ""  PC
 SG_ S2P_Cfg8_SW_Ver_Byte5_43 : 32|8@1+ (1,0) [0|255] ""  PC
 SG_ S2P_Cfg8_SW_Ver_Byte6_43 : 40|8@1+ (1,0) [0|255] ""  PC
 SG_ S2P_Cfg8_SW_Ver_Byte7_43 : 48|8@1+ (1,0) [0|255] ""  PC
 SG_ S2P_Cfg8_SW_Ver_Byte8_43 : 56|8@1+ (1,0) [0|255] ""  PC

BO_ 2417553004 S2P_Cfg8__44: 8 SBMU
 SG_ S2P_Cfg8_SW_Ver_Byte1_44 : 0|8@1+ (1,0) [0|255] ""  PC
 SG_ S2P_Cfg8_SW_Ver_Byte2_44 : 8|8@1+ (1,0) [0|255] ""  PC
 SG_ S2P_Cfg8_SW_Ver_Byte3_44 : 16|8@1+ (1,0) [0|255] ""  PC
 SG_ S2P_Cfg8_SW_Ver_Byte4_44 : 24|8@1+ (1,0) [0|255] ""  PC
 SG_ S2P_Cfg8_SW_Ver_Byte5_44 : 32|8@1+ (1,0) [0|255] ""  PC
 SG_ S2P_Cfg8_SW_Ver_Byte6_44 : 40|8@1+ (1,0) [0|255] ""  PC
 SG_ S2P_Cfg8_SW_Ver_Byte7_44 : 48|8@1+ (1,0) [0|255] ""  PC
 SG_ S2P_Cfg8_SW_Ver_Byte8_44 : 56|8@1+ (1,0) [0|255] ""  PC

BO_ 2417553005 S2P_Cfg8__45: 8 SBMU
 SG_ S2P_Cfg8_SW_Ver_Byte1_45 : 0|8@1+ (1,0) [0|255] ""  PC
 SG_ S2P_Cfg8_SW_Ver_Byte2_45 : 8|8@1+ (1,0) [0|255] ""  PC
 SG_ S2P_Cfg8_SW_Ver_Byte3_45 : 16|8@1+ (1,0) [0|255] ""  PC
 SG_ S2P_Cfg8_SW_Ver_Byte4_45 : 24|8@1+ (1,0) [0|255] ""  PC
 SG_ S2P_Cfg8_SW_Ver_Byte5_45 : 32|8@1+ (1,0) [0|255] ""  PC
 SG_ S2P_Cfg8_SW_Ver_Byte6_45 : 40|8@1+ (1,0) [0|255] ""  PC
 SG_ S2P_Cfg8_SW_Ver_Byte7_45 : 48|8@1+ (1,0) [0|255] ""  PC
 SG_ S2P_Cfg8_SW_Ver_Byte8_45 : 56|8@1+ (1,0) [0|255] ""  PC

BO_ 2417553006 S2P_Cfg8__46: 8 SBMU
 SG_ S2P_Cfg8_SW_Ver_Byte1_46 : 0|8@1+ (1,0) [0|255] ""  PC
 SG_ S2P_Cfg8_SW_Ver_Byte2_46 : 8|8@1+ (1,0) [0|255] ""  PC
 SG_ S2P_Cfg8_SW_Ver_Byte3_46 : 16|8@1+ (1,0) [0|255] ""  PC
 SG_ S2P_Cfg8_SW_Ver_Byte4_46 : 24|8@1+ (1,0) [0|255] ""  PC
 SG_ S2P_Cfg8_SW_Ver_Byte5_46 : 32|8@1+ (1,0) [0|255] ""  PC
 SG_ S2P_Cfg8_SW_Ver_Byte6_46 : 40|8@1+ (1,0) [0|255] ""  PC
 SG_ S2P_Cfg8_SW_Ver_Byte7_46 : 48|8@1+ (1,0) [0|255] ""  PC
 SG_ S2P_Cfg8_SW_Ver_Byte8_46 : 56|8@1+ (1,0) [0|255] ""  PC

BO_ 2417553007 S2P_Cfg8__47: 8 SBMU
 SG_ S2P_Cfg8_SW_Ver_Byte1_47 : 0|8@1+ (1,0) [0|255] ""  PC
 SG_ S2P_Cfg8_SW_Ver_Byte2_47 : 8|8@1+ (1,0) [0|255] ""  PC
 SG_ S2P_Cfg8_SW_Ver_Byte3_47 : 16|8@1+ (1,0) [0|255] ""  PC
 SG_ S2P_Cfg8_SW_Ver_Byte4_47 : 24|8@1+ (1,0) [0|255] ""  PC
 SG_ S2P_Cfg8_SW_Ver_Byte5_47 : 32|8@1+ (1,0) [0|255] ""  PC
 SG_ S2P_Cfg8_SW_Ver_Byte6_47 : 40|8@1+ (1,0) [0|255] ""  PC
 SG_ S2P_Cfg8_SW_Ver_Byte7_47 : 48|8@1+ (1,0) [0|255] ""  PC
 SG_ S2P_Cfg8_SW_Ver_Byte8_47 : 56|8@1+ (1,0) [0|255] ""  PC

BO_ 2417553008 S2P_Cfg8__48: 8 SBMU
 SG_ S2P_Cfg8_SW_Ver_Byte1_48 : 0|8@1+ (1,0) [0|255] ""  PC
 SG_ S2P_Cfg8_SW_Ver_Byte2_48 : 8|8@1+ (1,0) [0|255] ""  PC
 SG_ S2P_Cfg8_SW_Ver_Byte3_48 : 16|8@1+ (1,0) [0|255] ""  PC
 SG_ S2P_Cfg8_SW_Ver_Byte4_48 : 24|8@1+ (1,0) [0|255] ""  PC
 SG_ S2P_Cfg8_SW_Ver_Byte5_48 : 32|8@1+ (1,0) [0|255] ""  PC
 SG_ S2P_Cfg8_SW_Ver_Byte6_48 : 40|8@1+ (1,0) [0|255] ""  PC
 SG_ S2P_Cfg8_SW_Ver_Byte7_48 : 48|8@1+ (1,0) [0|255] ""  PC
 SG_ S2P_Cfg8_SW_Ver_Byte8_48 : 56|8@1+ (1,0) [0|255] ""  PC

BO_ 2417553009 S2P_Cfg8__49: 8 SBMU
 SG_ S2P_Cfg8_SW_Ver_Byte1_49 : 0|8@1+ (1,0) [0|255] ""  PC
 SG_ S2P_Cfg8_SW_Ver_Byte2_49 : 8|8@1+ (1,0) [0|255] ""  PC
 SG_ S2P_Cfg8_SW_Ver_Byte3_49 : 16|8@1+ (1,0) [0|255] ""  PC
 SG_ S2P_Cfg8_SW_Ver_Byte4_49 : 24|8@1+ (1,0) [0|255] ""  PC
 SG_ S2P_Cfg8_SW_Ver_Byte5_49 : 32|8@1+ (1,0) [0|255] ""  PC
 SG_ S2P_Cfg8_SW_Ver_Byte6_49 : 40|8@1+ (1,0) [0|255] ""  PC
 SG_ S2P_Cfg8_SW_Ver_Byte7_49 : 48|8@1+ (1,0) [0|255] ""  PC
 SG_ S2P_Cfg8_SW_Ver_Byte8_49 : 56|8@1+ (1,0) [0|255] ""  PC

BO_ 2417553010 S2P_Cfg8__50: 8 SBMU
 SG_ S2P_Cfg8_SW_Ver_Byte1_50 : 0|8@1+ (1,0) [0|255] ""  PC
 SG_ S2P_Cfg8_SW_Ver_Byte2_50 : 8|8@1+ (1,0) [0|255] ""  PC
 SG_ S2P_Cfg8_SW_Ver_Byte3_50 : 16|8@1+ (1,0) [0|255] ""  PC
 SG_ S2P_Cfg8_SW_Ver_Byte4_50 : 24|8@1+ (1,0) [0|255] ""  PC
 SG_ S2P_Cfg8_SW_Ver_Byte5_50 : 32|8@1+ (1,0) [0|255] ""  PC
 SG_ S2P_Cfg8_SW_Ver_Byte6_50 : 40|8@1+ (1,0) [0|255] ""  PC
 SG_ S2P_Cfg8_SW_Ver_Byte7_50 : 48|8@1+ (1,0) [0|255] ""  PC
 SG_ S2P_Cfg8_SW_Ver_Byte8_50 : 56|8@1+ (1,0) [0|255] ""  PC

BO_ 2417553011 S2P_Cfg8__51: 8 SBMU
 SG_ S2P_Cfg8_SW_Ver_Byte1_51 : 0|8@1+ (1,0) [0|255] ""  PC
 SG_ S2P_Cfg8_SW_Ver_Byte2_51 : 8|8@1+ (1,0) [0|255] ""  PC
 SG_ S2P_Cfg8_SW_Ver_Byte3_51 : 16|8@1+ (1,0) [0|255] ""  PC
 SG_ S2P_Cfg8_SW_Ver_Byte4_51 : 24|8@1+ (1,0) [0|255] ""  PC
 SG_ S2P_Cfg8_SW_Ver_Byte5_51 : 32|8@1+ (1,0) [0|255] ""  PC
 SG_ S2P_Cfg8_SW_Ver_Byte6_51 : 40|8@1+ (1,0) [0|255] ""  PC
 SG_ S2P_Cfg8_SW_Ver_Byte7_51 : 48|8@1+ (1,0) [0|255] ""  PC
 SG_ S2P_Cfg8_SW_Ver_Byte8_51 : 56|8@1+ (1,0) [0|255] ""  PC

BO_ 2417553012 S2P_Cfg8__52: 8 SBMU
 SG_ S2P_Cfg8_SW_Ver_Byte1_52 : 0|8@1+ (1,0) [0|255] ""  PC
 SG_ S2P_Cfg8_SW_Ver_Byte2_52 : 8|8@1+ (1,0) [0|255] ""  PC
 SG_ S2P_Cfg8_SW_Ver_Byte3_52 : 16|8@1+ (1,0) [0|255] ""  PC
 SG_ S2P_Cfg8_SW_Ver_Byte4_52 : 24|8@1+ (1,0) [0|255] ""  PC
 SG_ S2P_Cfg8_SW_Ver_Byte5_52 : 32|8@1+ (1,0) [0|255] ""  PC
 SG_ S2P_Cfg8_SW_Ver_Byte6_52 : 40|8@1+ (1,0) [0|255] ""  PC
 SG_ S2P_Cfg8_SW_Ver_Byte7_52 : 48|8@1+ (1,0) [0|255] ""  PC
 SG_ S2P_Cfg8_SW_Ver_Byte8_52 : 56|8@1+ (1,0) [0|255] ""  PC

BO_ 2417553013 S2P_Cfg8__53: 8 SBMU
 SG_ S2P_Cfg8_SW_Ver_Byte1_53 : 0|8@1+ (1,0) [0|255] ""  PC
 SG_ S2P_Cfg8_SW_Ver_Byte2_53 : 8|8@1+ (1,0) [0|255] ""  PC
 SG_ S2P_Cfg8_SW_Ver_Byte3_53 : 16|8@1+ (1,0) [0|255] ""  PC
 SG_ S2P_Cfg8_SW_Ver_Byte4_53 : 24|8@1+ (1,0) [0|255] ""  PC
 SG_ S2P_Cfg8_SW_Ver_Byte5_53 : 32|8@1+ (1,0) [0|255] ""  PC
 SG_ S2P_Cfg8_SW_Ver_Byte6_53 : 40|8@1+ (1,0) [0|255] ""  PC
 SG_ S2P_Cfg8_SW_Ver_Byte7_53 : 48|8@1+ (1,0) [0|255] ""  PC
 SG_ S2P_Cfg8_SW_Ver_Byte8_53 : 56|8@1+ (1,0) [0|255] ""  PC

BO_ 2417553014 S2P_Cfg8__54: 8 SBMU
 SG_ S2P_Cfg8_SW_Ver_Byte1_54 : 0|8@1+ (1,0) [0|255] ""  PC
 SG_ S2P_Cfg8_SW_Ver_Byte2_54 : 8|8@1+ (1,0) [0|255] ""  PC
 SG_ S2P_Cfg8_SW_Ver_Byte3_54 : 16|8@1+ (1,0) [0|255] ""  PC
 SG_ S2P_Cfg8_SW_Ver_Byte4_54 : 24|8@1+ (1,0) [0|255] ""  PC
 SG_ S2P_Cfg8_SW_Ver_Byte5_54 : 32|8@1+ (1,0) [0|255] ""  PC
 SG_ S2P_Cfg8_SW_Ver_Byte6_54 : 40|8@1+ (1,0) [0|255] ""  PC
 SG_ S2P_Cfg8_SW_Ver_Byte7_54 : 48|8@1+ (1,0) [0|255] ""  PC
 SG_ S2P_Cfg8_SW_Ver_Byte8_54 : 56|8@1+ (1,0) [0|255] ""  PC

BO_ 2417553015 S2P_Cfg8__55: 8 SBMU
 SG_ S2P_Cfg8_SW_Ver_Byte1_55 : 0|8@1+ (1,0) [0|255] ""  PC
 SG_ S2P_Cfg8_SW_Ver_Byte2_55 : 8|8@1+ (1,0) [0|255] ""  PC
 SG_ S2P_Cfg8_SW_Ver_Byte3_55 : 16|8@1+ (1,0) [0|255] ""  PC
 SG_ S2P_Cfg8_SW_Ver_Byte4_55 : 24|8@1+ (1,0) [0|255] ""  PC
 SG_ S2P_Cfg8_SW_Ver_Byte5_55 : 32|8@1+ (1,0) [0|255] ""  PC
 SG_ S2P_Cfg8_SW_Ver_Byte6_55 : 40|8@1+ (1,0) [0|255] ""  PC
 SG_ S2P_Cfg8_SW_Ver_Byte7_55 : 48|8@1+ (1,0) [0|255] ""  PC
 SG_ S2P_Cfg8_SW_Ver_Byte8_55 : 56|8@1+ (1,0) [0|255] ""  PC

BO_ 2417553016 S2P_Cfg8__56: 8 SBMU
 SG_ S2P_Cfg8_SW_Ver_Byte1_56 : 0|8@1+ (1,0) [0|255] ""  PC
 SG_ S2P_Cfg8_SW_Ver_Byte2_56 : 8|8@1+ (1,0) [0|255] ""  PC
 SG_ S2P_Cfg8_SW_Ver_Byte3_56 : 16|8@1+ (1,0) [0|255] ""  PC
 SG_ S2P_Cfg8_SW_Ver_Byte4_56 : 24|8@1+ (1,0) [0|255] ""  PC
 SG_ S2P_Cfg8_SW_Ver_Byte5_56 : 32|8@1+ (1,0) [0|255] ""  PC
 SG_ S2P_Cfg8_SW_Ver_Byte6_56 : 40|8@1+ (1,0) [0|255] ""  PC
 SG_ S2P_Cfg8_SW_Ver_Byte7_56 : 48|8@1+ (1,0) [0|255] ""  PC
 SG_ S2P_Cfg8_SW_Ver_Byte8_56 : 56|8@1+ (1,0) [0|255] ""  PC

BO_ 2417553017 S2P_Cfg8__57: 8 SBMU
 SG_ S2P_Cfg8_SW_Ver_Byte1_57 : 0|8@1+ (1,0) [0|255] ""  PC
 SG_ S2P_Cfg8_SW_Ver_Byte2_57 : 8|8@1+ (1,0) [0|255] ""  PC
 SG_ S2P_Cfg8_SW_Ver_Byte3_57 : 16|8@1+ (1,0) [0|255] ""  PC
 SG_ S2P_Cfg8_SW_Ver_Byte4_57 : 24|8@1+ (1,0) [0|255] ""  PC
 SG_ S2P_Cfg8_SW_Ver_Byte5_57 : 32|8@1+ (1,0) [0|255] ""  PC
 SG_ S2P_Cfg8_SW_Ver_Byte6_57 : 40|8@1+ (1,0) [0|255] ""  PC
 SG_ S2P_Cfg8_SW_Ver_Byte7_57 : 48|8@1+ (1,0) [0|255] ""  PC
 SG_ S2P_Cfg8_SW_Ver_Byte8_57 : 56|8@1+ (1,0) [0|255] ""  PC

BO_ 2417553018 S2P_Cfg8__58: 8 SBMU
 SG_ S2P_Cfg8_SW_Ver_Byte1_58 : 0|8@1+ (1,0) [0|255] ""  PC
 SG_ S2P_Cfg8_SW_Ver_Byte2_58 : 8|8@1+ (1,0) [0|255] ""  PC
 SG_ S2P_Cfg8_SW_Ver_Byte3_58 : 16|8@1+ (1,0) [0|255] ""  PC
 SG_ S2P_Cfg8_SW_Ver_Byte4_58 : 24|8@1+ (1,0) [0|255] ""  PC
 SG_ S2P_Cfg8_SW_Ver_Byte5_58 : 32|8@1+ (1,0) [0|255] ""  PC
 SG_ S2P_Cfg8_SW_Ver_Byte6_58 : 40|8@1+ (1,0) [0|255] ""  PC
 SG_ S2P_Cfg8_SW_Ver_Byte7_58 : 48|8@1+ (1,0) [0|255] ""  PC
 SG_ S2P_Cfg8_SW_Ver_Byte8_58 : 56|8@1+ (1,0) [0|255] ""  PC

BO_ 2417553019 S2P_Cfg8__59: 8 SBMU
 SG_ S2P_Cfg8_SW_Ver_Byte1_59 : 0|8@1+ (1,0) [0|255] ""  PC
 SG_ S2P_Cfg8_SW_Ver_Byte2_59 : 8|8@1+ (1,0) [0|255] ""  PC
 SG_ S2P_Cfg8_SW_Ver_Byte3_59 : 16|8@1+ (1,0) [0|255] ""  PC
 SG_ S2P_Cfg8_SW_Ver_Byte4_59 : 24|8@1+ (1,0) [0|255] ""  PC
 SG_ S2P_Cfg8_SW_Ver_Byte5_59 : 32|8@1+ (1,0) [0|255] ""  PC
 SG_ S2P_Cfg8_SW_Ver_Byte6_59 : 40|8@1+ (1,0) [0|255] ""  PC
 SG_ S2P_Cfg8_SW_Ver_Byte7_59 : 48|8@1+ (1,0) [0|255] ""  PC
 SG_ S2P_Cfg8_SW_Ver_Byte8_59 : 56|8@1+ (1,0) [0|255] ""  PC

BO_ 2417553020 S2P_Cfg8__60: 8 SBMU
 SG_ S2P_Cfg8_SW_Ver_Byte1_60 : 0|8@1+ (1,0) [0|255] ""  PC
 SG_ S2P_Cfg8_SW_Ver_Byte2_60 : 8|8@1+ (1,0) [0|255] ""  PC
 SG_ S2P_Cfg8_SW_Ver_Byte3_60 : 16|8@1+ (1,0) [0|255] ""  PC
 SG_ S2P_Cfg8_SW_Ver_Byte4_60 : 24|8@1+ (1,0) [0|255] ""  PC
 SG_ S2P_Cfg8_SW_Ver_Byte5_60 : 32|8@1+ (1,0) [0|255] ""  PC
 SG_ S2P_Cfg8_SW_Ver_Byte6_60 : 40|8@1+ (1,0) [0|255] ""  PC
 SG_ S2P_Cfg8_SW_Ver_Byte7_60 : 48|8@1+ (1,0) [0|255] ""  PC
 SG_ S2P_Cfg8_SW_Ver_Byte8_60 : 56|8@1+ (1,0) [0|255] ""  PC

BO_ 2417553021 S2P_Cfg8__61: 8 SBMU
 SG_ S2P_Cfg8_SW_Ver_Byte1_61 : 0|8@1+ (1,0) [0|255] ""  PC
 SG_ S2P_Cfg8_SW_Ver_Byte2_61 : 8|8@1+ (1,0) [0|255] ""  PC
 SG_ S2P_Cfg8_SW_Ver_Byte3_61 : 16|8@1+ (1,0) [0|255] ""  PC
 SG_ S2P_Cfg8_SW_Ver_Byte4_61 : 24|8@1+ (1,0) [0|255] ""  PC
 SG_ S2P_Cfg8_SW_Ver_Byte5_61 : 32|8@1+ (1,0) [0|255] ""  PC
 SG_ S2P_Cfg8_SW_Ver_Byte6_61 : 40|8@1+ (1,0) [0|255] ""  PC
 SG_ S2P_Cfg8_SW_Ver_Byte7_61 : 48|8@1+ (1,0) [0|255] ""  PC
 SG_ S2P_Cfg8_SW_Ver_Byte8_61 : 56|8@1+ (1,0) [0|255] ""  PC

BO_ 2417553022 S2P_Cfg8__62: 8 SBMU
 SG_ S2P_Cfg8_SW_Ver_Byte1_62 : 0|8@1+ (1,0) [0|255] ""  PC
 SG_ S2P_Cfg8_SW_Ver_Byte2_62 : 8|8@1+ (1,0) [0|255] ""  PC
 SG_ S2P_Cfg8_SW_Ver_Byte3_62 : 16|8@1+ (1,0) [0|255] ""  PC
 SG_ S2P_Cfg8_SW_Ver_Byte4_62 : 24|8@1+ (1,0) [0|255] ""  PC
 SG_ S2P_Cfg8_SW_Ver_Byte5_62 : 32|8@1+ (1,0) [0|255] ""  PC
 SG_ S2P_Cfg8_SW_Ver_Byte6_62 : 40|8@1+ (1,0) [0|255] ""  PC
 SG_ S2P_Cfg8_SW_Ver_Byte7_62 : 48|8@1+ (1,0) [0|255] ""  PC
 SG_ S2P_Cfg8_SW_Ver_Byte8_62 : 56|8@1+ (1,0) [0|255] ""  PC

BO_ 2417553023 S2P_Cfg8__63: 8 SBMU
 SG_ S2P_Cfg8_SW_Ver_Byte1_63 : 0|8@1+ (1,0) [0|255] ""  PC
 SG_ S2P_Cfg8_SW_Ver_Byte2_63 : 8|8@1+ (1,0) [0|255] ""  PC
 SG_ S2P_Cfg8_SW_Ver_Byte3_63 : 16|8@1+ (1,0) [0|255] ""  PC
 SG_ S2P_Cfg8_SW_Ver_Byte4_63 : 24|8@1+ (1,0) [0|255] ""  PC
 SG_ S2P_Cfg8_SW_Ver_Byte5_63 : 32|8@1+ (1,0) [0|255] ""  PC
 SG_ S2P_Cfg8_SW_Ver_Byte6_63 : 40|8@1+ (1,0) [0|255] ""  PC
 SG_ S2P_Cfg8_SW_Ver_Byte7_63 : 48|8@1+ (1,0) [0|255] ""  PC
 SG_ S2P_Cfg8_SW_Ver_Byte8_63 : 56|8@1+ (1,0) [0|255] ""  PC

BO_ 2417618497 S2P_Cfg9__01: 8 SBMU
 SG_ S2P_Cfg9_SW_Ver_Byte9_01 : 0|8@1+ (1,0) [0|255] ""  PC
 SG_ S2P_Cfg9_SW_Ver_Byte10_01 : 8|8@1+ (1,0) [0|255] ""  PC
 SG_ S2P_Cfg9_SW_Ver_Byte11_01 : 16|8@1+ (1,0) [0|255] ""  PC
 SG_ S2P_Cfg9_SW_Ver_Byte12_01 : 24|8@1+ (1,0) [0|255] ""  PC
 SG_ S2P_Cfg9_SW_Ver_Byte13_01 : 32|8@1+ (1,0) [0|255] ""  PC
 SG_ S2P_Cfg9_SW_Ver_Byte14_01 : 40|8@1+ (1,0) [0|255] ""  PC
 SG_ S2P_Cfg9_SW_Ver_Byte15_01 : 48|8@1+ (1,0) [0|255] ""  PC
 SG_ S2P_Cfg9_SW_Ver_Byte16_01 : 56|8@1+ (1,0) [0|255] ""  PC

BO_ 2417618498 S2P_Cfg9__02: 8 SBMU
 SG_ S2P_Cfg9_SW_Ver_Byte9_02 : 0|8@1+ (1,0) [0|255] ""  PC
 SG_ S2P_Cfg9_SW_Ver_Byte10_02 : 8|8@1+ (1,0) [0|255] ""  PC
 SG_ S2P_Cfg9_SW_Ver_Byte11_02 : 16|8@1+ (1,0) [0|255] ""  PC
 SG_ S2P_Cfg9_SW_Ver_Byte12_02 : 24|8@1+ (1,0) [0|255] ""  PC
 SG_ S2P_Cfg9_SW_Ver_Byte13_02 : 32|8@1+ (1,0) [0|255] ""  PC
 SG_ S2P_Cfg9_SW_Ver_Byte14_02 : 40|8@1+ (1,0) [0|255] ""  PC
 SG_ S2P_Cfg9_SW_Ver_Byte15_02 : 48|8@1+ (1,0) [0|255] ""  PC
 SG_ S2P_Cfg9_SW_Ver_Byte16_02 : 56|8@1+ (1,0) [0|255] ""  PC

BO_ 2417618499 S2P_Cfg9__03: 8 SBMU
 SG_ S2P_Cfg9_SW_Ver_Byte9_03 : 0|8@1+ (1,0) [0|255] ""  PC
 SG_ S2P_Cfg9_SW_Ver_Byte10_03 : 8|8@1+ (1,0) [0|255] ""  PC
 SG_ S2P_Cfg9_SW_Ver_Byte11_03 : 16|8@1+ (1,0) [0|255] ""  PC
 SG_ S2P_Cfg9_SW_Ver_Byte12_03 : 24|8@1+ (1,0) [0|255] ""  PC
 SG_ S2P_Cfg9_SW_Ver_Byte13_03 : 32|8@1+ (1,0) [0|255] ""  PC
 SG_ S2P_Cfg9_SW_Ver_Byte14_03 : 40|8@1+ (1,0) [0|255] ""  PC
 SG_ S2P_Cfg9_SW_Ver_Byte15_03 : 48|8@1+ (1,0) [0|255] ""  PC
 SG_ S2P_Cfg9_SW_Ver_Byte16_03 : 56|8@1+ (1,0) [0|255] ""  PC

BO_ 2417618500 S2P_Cfg9__04: 8 SBMU
 SG_ S2P_Cfg9_SW_Ver_Byte9_04 : 0|8@1+ (1,0) [0|255] ""  PC
 SG_ S2P_Cfg9_SW_Ver_Byte10_04 : 8|8@1+ (1,0) [0|255] ""  PC
 SG_ S2P_Cfg9_SW_Ver_Byte11_04 : 16|8@1+ (1,0) [0|255] ""  PC
 SG_ S2P_Cfg9_SW_Ver_Byte12_04 : 24|8@1+ (1,0) [0|255] ""  PC
 SG_ S2P_Cfg9_SW_Ver_Byte13_04 : 32|8@1+ (1,0) [0|255] ""  PC
 SG_ S2P_Cfg9_SW_Ver_Byte14_04 : 40|8@1+ (1,0) [0|255] ""  PC
 SG_ S2P_Cfg9_SW_Ver_Byte15_04 : 48|8@1+ (1,0) [0|255] ""  PC
 SG_ S2P_Cfg9_SW_Ver_Byte16_04 : 56|8@1+ (1,0) [0|255] ""  PC

BO_ 2417618501 S2P_Cfg9__05: 8 SBMU
 SG_ S2P_Cfg9_SW_Ver_Byte9_05 : 0|8@1+ (1,0) [0|255] ""  PC
 SG_ S2P_Cfg9_SW_Ver_Byte10_05 : 8|8@1+ (1,0) [0|255] ""  PC
 SG_ S2P_Cfg9_SW_Ver_Byte11_05 : 16|8@1+ (1,0) [0|255] ""  PC
 SG_ S2P_Cfg9_SW_Ver_Byte12_05 : 24|8@1+ (1,0) [0|255] ""  PC
 SG_ S2P_Cfg9_SW_Ver_Byte13_05 : 32|8@1+ (1,0) [0|255] ""  PC
 SG_ S2P_Cfg9_SW_Ver_Byte14_05 : 40|8@1+ (1,0) [0|255] ""  PC
 SG_ S2P_Cfg9_SW_Ver_Byte15_05 : 48|8@1+ (1,0) [0|255] ""  PC
 SG_ S2P_Cfg9_SW_Ver_Byte16_05 : 56|8@1+ (1,0) [0|255] ""  PC

BO_ 2417618502 S2P_Cfg9__06: 8 SBMU
 SG_ S2P_Cfg9_SW_Ver_Byte9_06 : 0|8@1+ (1,0) [0|255] ""  PC
 SG_ S2P_Cfg9_SW_Ver_Byte10_06 : 8|8@1+ (1,0) [0|255] ""  PC
 SG_ S2P_Cfg9_SW_Ver_Byte11_06 : 16|8@1+ (1,0) [0|255] ""  PC
 SG_ S2P_Cfg9_SW_Ver_Byte12_06 : 24|8@1+ (1,0) [0|255] ""  PC
 SG_ S2P_Cfg9_SW_Ver_Byte13_06 : 32|8@1+ (1,0) [0|255] ""  PC
 SG_ S2P_Cfg9_SW_Ver_Byte14_06 : 40|8@1+ (1,0) [0|255] ""  PC
 SG_ S2P_Cfg9_SW_Ver_Byte15_06 : 48|8@1+ (1,0) [0|255] ""  PC
 SG_ S2P_Cfg9_SW_Ver_Byte16_06 : 56|8@1+ (1,0) [0|255] ""  PC

BO_ 2417618503 S2P_Cfg9__07: 8 SBMU
 SG_ S2P_Cfg9_SW_Ver_Byte9_07 : 0|8@1+ (1,0) [0|255] ""  PC
 SG_ S2P_Cfg9_SW_Ver_Byte10_07 : 8|8@1+ (1,0) [0|255] ""  PC
 SG_ S2P_Cfg9_SW_Ver_Byte11_07 : 16|8@1+ (1,0) [0|255] ""  PC
 SG_ S2P_Cfg9_SW_Ver_Byte12_07 : 24|8@1+ (1,0) [0|255] ""  PC
 SG_ S2P_Cfg9_SW_Ver_Byte13_07 : 32|8@1+ (1,0) [0|255] ""  PC
 SG_ S2P_Cfg9_SW_Ver_Byte14_07 : 40|8@1+ (1,0) [0|255] ""  PC
 SG_ S2P_Cfg9_SW_Ver_Byte15_07 : 48|8@1+ (1,0) [0|255] ""  PC
 SG_ S2P_Cfg9_SW_Ver_Byte16_07 : 56|8@1+ (1,0) [0|255] ""  PC

BO_ 2417618504 S2P_Cfg9__08: 8 SBMU
 SG_ S2P_Cfg9_SW_Ver_Byte9_08 : 0|8@1+ (1,0) [0|255] ""  PC
 SG_ S2P_Cfg9_SW_Ver_Byte10_08 : 8|8@1+ (1,0) [0|255] ""  PC
 SG_ S2P_Cfg9_SW_Ver_Byte11_08 : 16|8@1+ (1,0) [0|255] ""  PC
 SG_ S2P_Cfg9_SW_Ver_Byte12_08 : 24|8@1+ (1,0) [0|255] ""  PC
 SG_ S2P_Cfg9_SW_Ver_Byte13_08 : 32|8@1+ (1,0) [0|255] ""  PC
 SG_ S2P_Cfg9_SW_Ver_Byte14_08 : 40|8@1+ (1,0) [0|255] ""  PC
 SG_ S2P_Cfg9_SW_Ver_Byte15_08 : 48|8@1+ (1,0) [0|255] ""  PC
 SG_ S2P_Cfg9_SW_Ver_Byte16_08 : 56|8@1+ (1,0) [0|255] ""  PC

BO_ 2417618505 S2P_Cfg9__09: 8 SBMU
 SG_ S2P_Cfg9_SW_Ver_Byte9_09 : 0|8@1+ (1,0) [0|255] ""  PC
 SG_ S2P_Cfg9_SW_Ver_Byte10_09 : 8|8@1+ (1,0) [0|255] ""  PC
 SG_ S2P_Cfg9_SW_Ver_Byte11_09 : 16|8@1+ (1,0) [0|255] ""  PC
 SG_ S2P_Cfg9_SW_Ver_Byte12_09 : 24|8@1+ (1,0) [0|255] ""  PC
 SG_ S2P_Cfg9_SW_Ver_Byte13_09 : 32|8@1+ (1,0) [0|255] ""  PC
 SG_ S2P_Cfg9_SW_Ver_Byte14_09 : 40|8@1+ (1,0) [0|255] ""  PC
 SG_ S2P_Cfg9_SW_Ver_Byte15_09 : 48|8@1+ (1,0) [0|255] ""  PC
 SG_ S2P_Cfg9_SW_Ver_Byte16_09 : 56|8@1+ (1,0) [0|255] ""  PC

BO_ 2417618506 S2P_Cfg9__10: 8 SBMU
 SG_ S2P_Cfg9_SW_Ver_Byte9_10 : 0|8@1+ (1,0) [0|255] ""  PC
 SG_ S2P_Cfg9_SW_Ver_Byte10_10 : 8|8@1+ (1,0) [0|255] ""  PC
 SG_ S2P_Cfg9_SW_Ver_Byte11_10 : 16|8@1+ (1,0) [0|255] ""  PC
 SG_ S2P_Cfg9_SW_Ver_Byte12_10 : 24|8@1+ (1,0) [0|255] ""  PC
 SG_ S2P_Cfg9_SW_Ver_Byte13_10 : 32|8@1+ (1,0) [0|255] ""  PC
 SG_ S2P_Cfg9_SW_Ver_Byte14_10 : 40|8@1+ (1,0) [0|255] ""  PC
 SG_ S2P_Cfg9_SW_Ver_Byte15_10 : 48|8@1+ (1,0) [0|255] ""  PC
 SG_ S2P_Cfg9_SW_Ver_Byte16_10 : 56|8@1+ (1,0) [0|255] ""  PC

BO_ 2417618507 S2P_Cfg9__11: 8 SBMU
 SG_ S2P_Cfg9_SW_Ver_Byte9_11 : 0|8@1+ (1,0) [0|255] ""  PC
 SG_ S2P_Cfg9_SW_Ver_Byte10_11 : 8|8@1+ (1,0) [0|255] ""  PC
 SG_ S2P_Cfg9_SW_Ver_Byte11_11 : 16|8@1+ (1,0) [0|255] ""  PC
 SG_ S2P_Cfg9_SW_Ver_Byte12_11 : 24|8@1+ (1,0) [0|255] ""  PC
 SG_ S2P_Cfg9_SW_Ver_Byte13_11 : 32|8@1+ (1,0) [0|255] ""  PC
 SG_ S2P_Cfg9_SW_Ver_Byte14_11 : 40|8@1+ (1,0) [0|255] ""  PC
 SG_ S2P_Cfg9_SW_Ver_Byte15_11 : 48|8@1+ (1,0) [0|255] ""  PC
 SG_ S2P_Cfg9_SW_Ver_Byte16_11 : 56|8@1+ (1,0) [0|255] ""  PC

BO_ 2417618508 S2P_Cfg9__12: 8 SBMU
 SG_ S2P_Cfg9_SW_Ver_Byte9_12 : 0|8@1+ (1,0) [0|255] ""  PC
 SG_ S2P_Cfg9_SW_Ver_Byte10_12 : 8|8@1+ (1,0) [0|255] ""  PC
 SG_ S2P_Cfg9_SW_Ver_Byte11_12 : 16|8@1+ (1,0) [0|255] ""  PC
 SG_ S2P_Cfg9_SW_Ver_Byte12_12 : 24|8@1+ (1,0) [0|255] ""  PC
 SG_ S2P_Cfg9_SW_Ver_Byte13_12 : 32|8@1+ (1,0) [0|255] ""  PC
 SG_ S2P_Cfg9_SW_Ver_Byte14_12 : 40|8@1+ (1,0) [0|255] ""  PC
 SG_ S2P_Cfg9_SW_Ver_Byte15_12 : 48|8@1+ (1,0) [0|255] ""  PC
 SG_ S2P_Cfg9_SW_Ver_Byte16_12 : 56|8@1+ (1,0) [0|255] ""  PC

BO_ 2417618509 S2P_Cfg9__13: 8 SBMU
 SG_ S2P_Cfg9_SW_Ver_Byte9_13 : 0|8@1+ (1,0) [0|255] ""  PC
 SG_ S2P_Cfg9_SW_Ver_Byte10_13 : 8|8@1+ (1,0) [0|255] ""  PC
 SG_ S2P_Cfg9_SW_Ver_Byte11_13 : 16|8@1+ (1,0) [0|255] ""  PC
 SG_ S2P_Cfg9_SW_Ver_Byte12_13 : 24|8@1+ (1,0) [0|255] ""  PC
 SG_ S2P_Cfg9_SW_Ver_Byte13_13 : 32|8@1+ (1,0) [0|255] ""  PC
 SG_ S2P_Cfg9_SW_Ver_Byte14_13 : 40|8@1+ (1,0) [0|255] ""  PC
 SG_ S2P_Cfg9_SW_Ver_Byte15_13 : 48|8@1+ (1,0) [0|255] ""  PC
 SG_ S2P_Cfg9_SW_Ver_Byte16_13 : 56|8@1+ (1,0) [0|255] ""  PC

BO_ 2417618510 S2P_Cfg9__14: 8 SBMU
 SG_ S2P_Cfg9_SW_Ver_Byte9_14 : 0|8@1+ (1,0) [0|255] ""  PC
 SG_ S2P_Cfg9_SW_Ver_Byte10_14 : 8|8@1+ (1,0) [0|255] ""  PC
 SG_ S2P_Cfg9_SW_Ver_Byte11_14 : 16|8@1+ (1,0) [0|255] ""  PC
 SG_ S2P_Cfg9_SW_Ver_Byte12_14 : 24|8@1+ (1,0) [0|255] ""  PC
 SG_ S2P_Cfg9_SW_Ver_Byte13_14 : 32|8@1+ (1,0) [0|255] ""  PC
 SG_ S2P_Cfg9_SW_Ver_Byte14_14 : 40|8@1+ (1,0) [0|255] ""  PC
 SG_ S2P_Cfg9_SW_Ver_Byte15_14 : 48|8@1+ (1,0) [0|255] ""  PC
 SG_ S2P_Cfg9_SW_Ver_Byte16_14 : 56|8@1+ (1,0) [0|255] ""  PC

BO_ 2417618511 S2P_Cfg9__15: 8 SBMU
 SG_ S2P_Cfg9_SW_Ver_Byte9_15 : 0|8@1+ (1,0) [0|255] ""  PC
 SG_ S2P_Cfg9_SW_Ver_Byte10_15 : 8|8@1+ (1,0) [0|255] ""  PC
 SG_ S2P_Cfg9_SW_Ver_Byte11_15 : 16|8@1+ (1,0) [0|255] ""  PC
 SG_ S2P_Cfg9_SW_Ver_Byte12_15 : 24|8@1+ (1,0) [0|255] ""  PC
 SG_ S2P_Cfg9_SW_Ver_Byte13_15 : 32|8@1+ (1,0) [0|255] ""  PC
 SG_ S2P_Cfg9_SW_Ver_Byte14_15 : 40|8@1+ (1,0) [0|255] ""  PC
 SG_ S2P_Cfg9_SW_Ver_Byte15_15 : 48|8@1+ (1,0) [0|255] ""  PC
 SG_ S2P_Cfg9_SW_Ver_Byte16_15 : 56|8@1+ (1,0) [0|255] ""  PC

BO_ 2417618512 S2P_Cfg9__16: 8 SBMU
 SG_ S2P_Cfg9_SW_Ver_Byte9_16 : 0|8@1+ (1,0) [0|255] ""  PC
 SG_ S2P_Cfg9_SW_Ver_Byte10_16 : 8|8@1+ (1,0) [0|255] ""  PC
 SG_ S2P_Cfg9_SW_Ver_Byte11_16 : 16|8@1+ (1,0) [0|255] ""  PC
 SG_ S2P_Cfg9_SW_Ver_Byte12_16 : 24|8@1+ (1,0) [0|255] ""  PC
 SG_ S2P_Cfg9_SW_Ver_Byte13_16 : 32|8@1+ (1,0) [0|255] ""  PC
 SG_ S2P_Cfg9_SW_Ver_Byte14_16 : 40|8@1+ (1,0) [0|255] ""  PC
 SG_ S2P_Cfg9_SW_Ver_Byte15_16 : 48|8@1+ (1,0) [0|255] ""  PC
 SG_ S2P_Cfg9_SW_Ver_Byte16_16 : 56|8@1+ (1,0) [0|255] ""  PC

BO_ 2417618513 S2P_Cfg9__17: 8 SBMU
 SG_ S2P_Cfg9_SW_Ver_Byte9_17 : 0|8@1+ (1,0) [0|255] ""  PC
 SG_ S2P_Cfg9_SW_Ver_Byte10_17 : 8|8@1+ (1,0) [0|255] ""  PC
 SG_ S2P_Cfg9_SW_Ver_Byte11_17 : 16|8@1+ (1,0) [0|255] ""  PC
 SG_ S2P_Cfg9_SW_Ver_Byte12_17 : 24|8@1+ (1,0) [0|255] ""  PC
 SG_ S2P_Cfg9_SW_Ver_Byte13_17 : 32|8@1+ (1,0) [0|255] ""  PC
 SG_ S2P_Cfg9_SW_Ver_Byte14_17 : 40|8@1+ (1,0) [0|255] ""  PC
 SG_ S2P_Cfg9_SW_Ver_Byte15_17 : 48|8@1+ (1,0) [0|255] ""  PC
 SG_ S2P_Cfg9_SW_Ver_Byte16_17 : 56|8@1+ (1,0) [0|255] ""  PC

BO_ 2417618514 S2P_Cfg9__18: 8 SBMU
 SG_ S2P_Cfg9_SW_Ver_Byte9_18 : 0|8@1+ (1,0) [0|255] ""  PC
 SG_ S2P_Cfg9_SW_Ver_Byte10_18 : 8|8@1+ (1,0) [0|255] ""  PC
 SG_ S2P_Cfg9_SW_Ver_Byte11_18 : 16|8@1+ (1,0) [0|255] ""  PC
 SG_ S2P_Cfg9_SW_Ver_Byte12_18 : 24|8@1+ (1,0) [0|255] ""  PC
 SG_ S2P_Cfg9_SW_Ver_Byte13_18 : 32|8@1+ (1,0) [0|255] ""  PC
 SG_ S2P_Cfg9_SW_Ver_Byte14_18 : 40|8@1+ (1,0) [0|255] ""  PC
 SG_ S2P_Cfg9_SW_Ver_Byte15_18 : 48|8@1+ (1,0) [0|255] ""  PC
 SG_ S2P_Cfg9_SW_Ver_Byte16_18 : 56|8@1+ (1,0) [0|255] ""  PC

BO_ 2417618515 S2P_Cfg9__19: 8 SBMU
 SG_ S2P_Cfg9_SW_Ver_Byte9_19 : 0|8@1+ (1,0) [0|255] ""  PC
 SG_ S2P_Cfg9_SW_Ver_Byte10_19 : 8|8@1+ (1,0) [0|255] ""  PC
 SG_ S2P_Cfg9_SW_Ver_Byte11_19 : 16|8@1+ (1,0) [0|255] ""  PC
 SG_ S2P_Cfg9_SW_Ver_Byte12_19 : 24|8@1+ (1,0) [0|255] ""  PC
 SG_ S2P_Cfg9_SW_Ver_Byte13_19 : 32|8@1+ (1,0) [0|255] ""  PC
 SG_ S2P_Cfg9_SW_Ver_Byte14_19 : 40|8@1+ (1,0) [0|255] ""  PC
 SG_ S2P_Cfg9_SW_Ver_Byte15_19 : 48|8@1+ (1,0) [0|255] ""  PC
 SG_ S2P_Cfg9_SW_Ver_Byte16_19 : 56|8@1+ (1,0) [0|255] ""  PC

BO_ 2417618516 S2P_Cfg9__20: 8 SBMU
 SG_ S2P_Cfg9_SW_Ver_Byte9_20 : 0|8@1+ (1,0) [0|255] ""  PC
 SG_ S2P_Cfg9_SW_Ver_Byte10_20 : 8|8@1+ (1,0) [0|255] ""  PC
 SG_ S2P_Cfg9_SW_Ver_Byte11_20 : 16|8@1+ (1,0) [0|255] ""  PC
 SG_ S2P_Cfg9_SW_Ver_Byte12_20 : 24|8@1+ (1,0) [0|255] ""  PC
 SG_ S2P_Cfg9_SW_Ver_Byte13_20 : 32|8@1+ (1,0) [0|255] ""  PC
 SG_ S2P_Cfg9_SW_Ver_Byte14_20 : 40|8@1+ (1,0) [0|255] ""  PC
 SG_ S2P_Cfg9_SW_Ver_Byte15_20 : 48|8@1+ (1,0) [0|255] ""  PC
 SG_ S2P_Cfg9_SW_Ver_Byte16_20 : 56|8@1+ (1,0) [0|255] ""  PC

BO_ 2417618517 S2P_Cfg9__21: 8 SBMU
 SG_ S2P_Cfg9_SW_Ver_Byte9_21 : 0|8@1+ (1,0) [0|255] ""  PC
 SG_ S2P_Cfg9_SW_Ver_Byte10_21 : 8|8@1+ (1,0) [0|255] ""  PC
 SG_ S2P_Cfg9_SW_Ver_Byte11_21 : 16|8@1+ (1,0) [0|255] ""  PC
 SG_ S2P_Cfg9_SW_Ver_Byte12_21 : 24|8@1+ (1,0) [0|255] ""  PC
 SG_ S2P_Cfg9_SW_Ver_Byte13_21 : 32|8@1+ (1,0) [0|255] ""  PC
 SG_ S2P_Cfg9_SW_Ver_Byte14_21 : 40|8@1+ (1,0) [0|255] ""  PC
 SG_ S2P_Cfg9_SW_Ver_Byte15_21 : 48|8@1+ (1,0) [0|255] ""  PC
 SG_ S2P_Cfg9_SW_Ver_Byte16_21 : 56|8@1+ (1,0) [0|255] ""  PC

CM_ SG_ 2416373337 S2P_Cfg5_SBMU_Add_25 "SBMU的地址";
CM_ SG_ 2416373337 S2P_Cfg5_ModuleParal_Num_25 "当前SBMU模组并联数量？确认内容 wgw:PAL_CSC_COUNT固定为1";
CM_ SG_ 2416373337 S2P_Cfg5_CellSeries_Num_25 "电柜串联电芯数   CELL_NO *NUM_OF_CSC";
CM_ SG_ 2416373337 S2P_Cfg5_Temps_Num_25 "当前SBMU管理的环境温度采样点数目";
CM_ SG_ 2416373337 S2P_Cfg5_CSCs_Num_25 "当前SBMU管理的CSC数目";
CM_ SG_ 2416373337 S2P_Cfg5_Utank_Norminal_25 "分柜标称电压";
CM_ SG_ 2416373337 S2P_Cfg5_CSCType_25 "CSC类型";
CM_ SG_ 2416373338 S2P_Cfg5_SBMU_Add_26 "SBMU的地址";
CM_ SG_ 2416373338 S2P_Cfg5_ModuleParal_Num_26 "当前SBMU模组并联数量？确认内容 wgw:PAL_CSC_COUNT固定为1";
CM_ SG_ 2416373338 S2P_Cfg5_CellSeries_Num_26 "电柜串联电芯数   CELL_NO *NUM_OF_CSC";
CM_ SG_ 2416373338 S2P_Cfg5_Temps_Num_26 "当前SBMU管理的环境温度采样点数目";
CM_ SG_ 2416373338 S2P_Cfg5_CSCs_Num_26 "当前SBMU管理的CSC数目";
CM_ SG_ 2416373338 S2P_Cfg5_Utank_Norminal_26 "分柜标称电压";
CM_ SG_ 2416373338 S2P_Cfg5_CSCType_26 "CSC类型";
CM_ SG_ 2416373339 S2P_Cfg5_SBMU_Add_27 "SBMU的地址";
CM_ SG_ 2416373339 S2P_Cfg5_ModuleParal_Num_27 "当前SBMU模组并联数量？确认内容 wgw:PAL_CSC_COUNT固定为1";
CM_ SG_ 2416373339 S2P_Cfg5_CellSeries_Num_27 "电柜串联电芯数   CELL_NO *NUM_OF_CSC";
CM_ SG_ 2416373339 S2P_Cfg5_Temps_Num_27 "当前SBMU管理的环境温度采样点数目";
CM_ SG_ 2416373339 S2P_Cfg5_CSCs_Num_27 "当前SBMU管理的CSC数目";
CM_ SG_ 2416373339 S2P_Cfg5_Utank_Norminal_27 "分柜标称电压";
CM_ SG_ 2416373339 S2P_Cfg5_CSCType_27 "CSC类型";
CM_ SG_ 2416373340 S2P_Cfg5_SBMU_Add_28 "SBMU的地址";
CM_ SG_ 2416373340 S2P_Cfg5_ModuleParal_Num_28 "当前SBMU模组并联数量？确认内容 wgw:PAL_CSC_COUNT固定为1";
CM_ SG_ 2416373340 S2P_Cfg5_CellSeries_Num_28 "电柜串联电芯数   CELL_NO *NUM_OF_CSC";
CM_ SG_ 2416373340 S2P_Cfg5_Temps_Num_28 "当前SBMU管理的环境温度采样点数目";
CM_ SG_ 2416373340 S2P_Cfg5_CSCs_Num_28 "当前SBMU管理的CSC数目";
CM_ SG_ 2416373340 S2P_Cfg5_Utank_Norminal_28 "分柜标称电压";
CM_ SG_ 2416373340 S2P_Cfg5_CSCType_28 "CSC类型";
CM_ SG_ 2416373341 S2P_Cfg5_SBMU_Add_29 "SBMU的地址";
CM_ SG_ 2416373341 S2P_Cfg5_ModuleParal_Num_29 "当前SBMU模组并联数量？确认内容 wgw:PAL_CSC_COUNT固定为1";
CM_ SG_ 2416373341 S2P_Cfg5_CellSeries_Num_29 "电柜串联电芯数   CELL_NO *NUM_OF_CSC";
CM_ SG_ 2416373341 S2P_Cfg5_Temps_Num_29 "当前SBMU管理的环境温度采样点数目";
CM_ SG_ 2416373341 S2P_Cfg5_CSCs_Num_29 "当前SBMU管理的CSC数目";
CM_ SG_ 2416373341 S2P_Cfg5_Utank_Norminal_29 "分柜标称电压";
CM_ SG_ 2416373341 S2P_Cfg5_CSCType_29 "CSC类型";
CM_ SG_ 2416373342 S2P_Cfg5_SBMU_Add_30 "SBMU的地址";
CM_ SG_ 2416373342 S2P_Cfg5_ModuleParal_Num_30 "当前SBMU模组并联数量？确认内容 wgw:PAL_CSC_COUNT固定为1";
CM_ SG_ 2416373342 S2P_Cfg5_CellSeries_Num_30 "电柜串联电芯数   CELL_NO *NUM_OF_CSC";
CM_ SG_ 2416373342 S2P_Cfg5_Temps_Num_30 "当前SBMU管理的环境温度采样点数目";
CM_ SG_ 2416373342 S2P_Cfg5_CSCs_Num_30 "当前SBMU管理的CSC数目";
CM_ SG_ 2416373342 S2P_Cfg5_Utank_Norminal_30 "分柜标称电压";
CM_ SG_ 2416373342 S2P_Cfg5_CSCType_30 "CSC类型";
CM_ SG_ 2416373343 S2P_Cfg5_SBMU_Add_31 "SBMU的地址";
CM_ SG_ 2416373343 S2P_Cfg5_ModuleParal_Num_31 "当前SBMU模组并联数量？确认内容 wgw:PAL_CSC_COUNT固定为1";
CM_ SG_ 2416373343 S2P_Cfg5_CellSeries_Num_31 "电柜串联电芯数   CELL_NO *NUM_OF_CSC";
CM_ SG_ 2416373343 S2P_Cfg5_Temps_Num_31 "当前SBMU管理的环境温度采样点数目";
CM_ SG_ 2416373343 S2P_Cfg5_CSCs_Num_31 "当前SBMU管理的CSC数目";
CM_ SG_ 2416373343 S2P_Cfg5_Utank_Norminal_31 "分柜标称电压";
CM_ SG_ 2416373343 S2P_Cfg5_CSCType_31 "CSC类型";
CM_ SG_ 2416373344 S2P_Cfg5_SBMU_Add_32 "SBMU的地址";
CM_ SG_ 2416373344 S2P_Cfg5_ModuleParal_Num_32 "当前SBMU模组并联数量？确认内容 wgw:PAL_CSC_COUNT固定为1";
CM_ SG_ 2416373344 S2P_Cfg5_CellSeries_Num_32 "电柜串联电芯数   CELL_NO *NUM_OF_CSC";
CM_ SG_ 2416373344 S2P_Cfg5_Temps_Num_32 "当前SBMU管理的环境温度采样点数目";
CM_ SG_ 2416373344 S2P_Cfg5_CSCs_Num_32 "当前SBMU管理的CSC数目";
CM_ SG_ 2416373344 S2P_Cfg5_Utank_Norminal_32 "分柜标称电压";
CM_ SG_ 2416373344 S2P_Cfg5_CSCType_32 "CSC类型";
CM_ SG_ 2416373345 S2P_Cfg5_SBMU_Add_33 "SBMU的地址";
CM_ SG_ 2416373345 S2P_Cfg5_ModuleParal_Num_33 "当前SBMU模组并联数量？确认内容 wgw:PAL_CSC_COUNT固定为1";
CM_ SG_ 2416373345 S2P_Cfg5_CellSeries_Num_33 "电柜串联电芯数   CELL_NO *NUM_OF_CSC";
CM_ SG_ 2416373345 S2P_Cfg5_Temps_Num_33 "当前SBMU管理的环境温度采样点数目";
CM_ SG_ 2416373345 S2P_Cfg5_CSCs_Num_33 "当前SBMU管理的CSC数目";
CM_ SG_ 2416373345 S2P_Cfg5_Utank_Norminal_33 "分柜标称电压";
CM_ SG_ 2416373345 S2P_Cfg5_CSCType_33 "CSC类型";
CM_ SG_ 2416373346 S2P_Cfg5_SBMU_Add_34 "SBMU的地址";
CM_ SG_ 2416373346 S2P_Cfg5_ModuleParal_Num_34 "当前SBMU模组并联数量？确认内容 wgw:PAL_CSC_COUNT固定为1";
CM_ SG_ 2416373346 S2P_Cfg5_CellSeries_Num_34 "电柜串联电芯数   CELL_NO *NUM_OF_CSC";
CM_ SG_ 2416373346 S2P_Cfg5_Temps_Num_34 "当前SBMU管理的环境温度采样点数目";
CM_ SG_ 2416373346 S2P_Cfg5_CSCs_Num_34 "当前SBMU管理的CSC数目";
CM_ SG_ 2416373346 S2P_Cfg5_Utank_Norminal_34 "分柜标称电压";
CM_ SG_ 2416373346 S2P_Cfg5_CSCType_34 "CSC类型";
CM_ SG_ 2416373347 S2P_Cfg5_SBMU_Add_35 "SBMU的地址";
CM_ SG_ 2416373347 S2P_Cfg5_ModuleParal_Num_35 "当前SBMU模组并联数量？确认内容 wgw:PAL_CSC_COUNT固定为1";
CM_ SG_ 2416373347 S2P_Cfg5_CellSeries_Num_35 "电柜串联电芯数   CELL_NO *NUM_OF_CSC";
CM_ SG_ 2416373347 S2P_Cfg5_Temps_Num_35 "当前SBMU管理的环境温度采样点数目";
CM_ SG_ 2416373347 S2P_Cfg5_CSCs_Num_35 "当前SBMU管理的CSC数目";
CM_ SG_ 2416373347 S2P_Cfg5_Utank_Norminal_35 "分柜标称电压";
CM_ SG_ 2416373347 S2P_Cfg5_CSCType_35 "CSC类型";
CM_ SG_ 2416373348 S2P_Cfg5_SBMU_Add_36 "SBMU的地址";
CM_ SG_ 2416373348 S2P_Cfg5_ModuleParal_Num_36 "当前SBMU模组并联数量？确认内容 wgw:PAL_CSC_COUNT固定为1";
CM_ SG_ 2416373348 S2P_Cfg5_CellSeries_Num_36 "电柜串联电芯数   CELL_NO *NUM_OF_CSC";
CM_ SG_ 2416373348 S2P_Cfg5_Temps_Num_36 "当前SBMU管理的环境温度采样点数目";
CM_ SG_ 2416373348 S2P_Cfg5_CSCs_Num_36 "当前SBMU管理的CSC数目";
CM_ SG_ 2416373348 S2P_Cfg5_Utank_Norminal_36 "分柜标称电压";
CM_ SG_ 2416373348 S2P_Cfg5_CSCType_36 "CSC类型";
CM_ SG_ 2416373349 S2P_Cfg5_SBMU_Add_37 "SBMU的地址";
CM_ SG_ 2416373349 S2P_Cfg5_ModuleParal_Num_37 "当前SBMU模组并联数量？确认内容 wgw:PAL_CSC_COUNT固定为1";
CM_ SG_ 2416373349 S2P_Cfg5_CellSeries_Num_37 "电柜串联电芯数   CELL_NO *NUM_OF_CSC";
CM_ SG_ 2416373349 S2P_Cfg5_Temps_Num_37 "当前SBMU管理的环境温度采样点数目";
CM_ SG_ 2416373349 S2P_Cfg5_CSCs_Num_37 "当前SBMU管理的CSC数目";
CM_ SG_ 2416373349 S2P_Cfg5_Utank_Norminal_37 "分柜标称电压";
CM_ SG_ 2416373349 S2P_Cfg5_CSCType_37 "CSC类型";
CM_ SG_ 2416373350 S2P_Cfg5_SBMU_Add_38 "SBMU的地址";
CM_ SG_ 2416373350 S2P_Cfg5_ModuleParal_Num_38 "当前SBMU模组并联数量？确认内容 wgw:PAL_CSC_COUNT固定为1";
CM_ SG_ 2416373350 S2P_Cfg5_CellSeries_Num_38 "电柜串联电芯数   CELL_NO *NUM_OF_CSC";
CM_ SG_ 2416373350 S2P_Cfg5_Temps_Num_38 "当前SBMU管理的环境温度采样点数目";
CM_ SG_ 2416373350 S2P_Cfg5_CSCs_Num_38 "当前SBMU管理的CSC数目";
CM_ SG_ 2416373350 S2P_Cfg5_Utank_Norminal_38 "分柜标称电压";
CM_ SG_ 2416373350 S2P_Cfg5_CSCType_38 "CSC类型";
CM_ SG_ 2416373351 S2P_Cfg5_SBMU_Add_39 "SBMU的地址";
CM_ SG_ 2416373351 S2P_Cfg5_ModuleParal_Num_39 "当前SBMU模组并联数量？确认内容 wgw:PAL_CSC_COUNT固定为1";
CM_ SG_ 2416373351 S2P_Cfg5_CellSeries_Num_39 "电柜串联电芯数   CELL_NO *NUM_OF_CSC";
CM_ SG_ 2416373351 S2P_Cfg5_Temps_Num_39 "当前SBMU管理的环境温度采样点数目";
CM_ SG_ 2416373351 S2P_Cfg5_CSCs_Num_39 "当前SBMU管理的CSC数目";
CM_ SG_ 2416373351 S2P_Cfg5_Utank_Norminal_39 "分柜标称电压";
CM_ SG_ 2416373351 S2P_Cfg5_CSCType_39 "CSC类型";
CM_ SG_ 2416373352 S2P_Cfg5_SBMU_Add_40 "SBMU的地址";
CM_ SG_ 2416373352 S2P_Cfg5_ModuleParal_Num_40 "当前SBMU模组并联数量？确认内容 wgw:PAL_CSC_COUNT固定为1";
CM_ SG_ 2416373352 S2P_Cfg5_CellSeries_Num_40 "电柜串联电芯数   CELL_NO *NUM_OF_CSC";
CM_ SG_ 2416373352 S2P_Cfg5_Temps_Num_40 "当前SBMU管理的环境温度采样点数目";
CM_ SG_ 2416373352 S2P_Cfg5_CSCs_Num_40 "当前SBMU管理的CSC数目";
CM_ SG_ 2416373352 S2P_Cfg5_Utank_Norminal_40 "分柜标称电压";
CM_ SG_ 2416373352 S2P_Cfg5_CSCType_40 "CSC类型";
CM_ SG_ 2416373353 S2P_Cfg5_SBMU_Add_41 "SBMU的地址";
CM_ SG_ 2416373353 S2P_Cfg5_ModuleParal_Num_41 "当前SBMU模组并联数量？确认内容 wgw:PAL_CSC_COUNT固定为1";
CM_ SG_ 2416373353 S2P_Cfg5_CellSeries_Num_41 "电柜串联电芯数   CELL_NO *NUM_OF_CSC";
CM_ SG_ 2416373353 S2P_Cfg5_Temps_Num_41 "当前SBMU管理的环境温度采样点数目";
CM_ SG_ 2416373353 S2P_Cfg5_CSCs_Num_41 "当前SBMU管理的CSC数目";
CM_ SG_ 2416373353 S2P_Cfg5_Utank_Norminal_41 "分柜标称电压";
CM_ SG_ 2416373353 S2P_Cfg5_CSCType_41 "CSC类型";
CM_ SG_ 2416373354 S2P_Cfg5_SBMU_Add_42 "SBMU的地址";
CM_ SG_ 2416373354 S2P_Cfg5_ModuleParal_Num_42 "当前SBMU模组并联数量？确认内容 wgw:PAL_CSC_COUNT固定为1";
CM_ SG_ 2416373354 S2P_Cfg5_CellSeries_Num_42 "电柜串联电芯数   CELL_NO *NUM_OF_CSC";
CM_ SG_ 2416373354 S2P_Cfg5_Temps_Num_42 "当前SBMU管理的环境温度采样点数目";
CM_ SG_ 2416373354 S2P_Cfg5_CSCs_Num_42 "当前SBMU管理的CSC数目";
CM_ SG_ 2416373354 S2P_Cfg5_Utank_Norminal_42 "分柜标称电压";
CM_ SG_ 2416373354 S2P_Cfg5_CSCType_42 "CSC类型";
CM_ SG_ 2416373355 S2P_Cfg5_SBMU_Add_43 "SBMU的地址";
CM_ SG_ 2416373355 S2P_Cfg5_ModuleParal_Num_43 "当前SBMU模组并联数量？确认内容 wgw:PAL_CSC_COUNT固定为1";
CM_ SG_ 2416373355 S2P_Cfg5_CellSeries_Num_43 "电柜串联电芯数   CELL_NO *NUM_OF_CSC";
CM_ SG_ 2416373355 S2P_Cfg5_Temps_Num_43 "当前SBMU管理的环境温度采样点数目";
CM_ SG_ 2416373355 S2P_Cfg5_CSCs_Num_43 "当前SBMU管理的CSC数目";
CM_ SG_ 2416373355 S2P_Cfg5_Utank_Norminal_43 "分柜标称电压";
CM_ SG_ 2416373355 S2P_Cfg5_CSCType_43 "CSC类型";
CM_ SG_ 2416373356 S2P_Cfg5_SBMU_Add_44 "SBMU的地址";
CM_ SG_ 2416373356 S2P_Cfg5_ModuleParal_Num_44 "当前SBMU模组并联数量？确认内容 wgw:PAL_CSC_COUNT固定为1";
CM_ SG_ 2416373356 S2P_Cfg5_CellSeries_Num_44 "电柜串联电芯数   CELL_NO *NUM_OF_CSC";
CM_ SG_ 2416373356 S2P_Cfg5_Temps_Num_44 "当前SBMU管理的环境温度采样点数目";
CM_ SG_ 2416373356 S2P_Cfg5_CSCs_Num_44 "当前SBMU管理的CSC数目";
CM_ SG_ 2416373356 S2P_Cfg5_Utank_Norminal_44 "分柜标称电压";
CM_ SG_ 2416373356 S2P_Cfg5_CSCType_44 "CSC类型";
CM_ SG_ 2416373357 S2P_Cfg5_SBMU_Add_45 "SBMU的地址";
CM_ SG_ 2416373357 S2P_Cfg5_ModuleParal_Num_45 "当前SBMU模组并联数量？确认内容 wgw:PAL_CSC_COUNT固定为1";
CM_ SG_ 2416373357 S2P_Cfg5_CellSeries_Num_45 "电柜串联电芯数   CELL_NO *NUM_OF_CSC";
CM_ SG_ 2416373357 S2P_Cfg5_Temps_Num_45 "当前SBMU管理的环境温度采样点数目";
CM_ SG_ 2416373357 S2P_Cfg5_CSCs_Num_45 "当前SBMU管理的CSC数目";
CM_ SG_ 2416373357 S2P_Cfg5_Utank_Norminal_45 "分柜标称电压";
CM_ SG_ 2416373357 S2P_Cfg5_CSCType_45 "CSC类型";
CM_ SG_ 2416373358 S2P_Cfg5_SBMU_Add_46 "SBMU的地址";
CM_ SG_ 2416373358 S2P_Cfg5_ModuleParal_Num_46 "当前SBMU模组并联数量？确认内容 wgw:PAL_CSC_COUNT固定为1";
CM_ SG_ 2416373358 S2P_Cfg5_CellSeries_Num_46 "电柜串联电芯数   CELL_NO *NUM_OF_CSC";
CM_ SG_ 2416373358 S2P_Cfg5_Temps_Num_46 "当前SBMU管理的环境温度采样点数目";
CM_ SG_ 2416373358 S2P_Cfg5_CSCs_Num_46 "当前SBMU管理的CSC数目";
CM_ SG_ 2416373358 S2P_Cfg5_Utank_Norminal_46 "分柜标称电压";
CM_ SG_ 2416373358 S2P_Cfg5_CSCType_46 "CSC类型";
CM_ SG_ 2416373359 S2P_Cfg5_SBMU_Add_47 "SBMU的地址";
CM_ SG_ 2416373359 S2P_Cfg5_ModuleParal_Num_47 "当前SBMU模组并联数量？确认内容 wgw:PAL_CSC_COUNT固定为1";
CM_ SG_ 2416373359 S2P_Cfg5_CellSeries_Num_47 "电柜串联电芯数   CELL_NO *NUM_OF_CSC";
CM_ SG_ 2416373359 S2P_Cfg5_Temps_Num_47 "当前SBMU管理的环境温度采样点数目";
CM_ SG_ 2416373359 S2P_Cfg5_CSCs_Num_47 "当前SBMU管理的CSC数目";
CM_ SG_ 2416373359 S2P_Cfg5_Utank_Norminal_47 "分柜标称电压";
CM_ SG_ 2416373359 S2P_Cfg5_CSCType_47 "CSC类型";
CM_ SG_ 2416373360 S2P_Cfg5_SBMU_Add_48 "SBMU的地址";
CM_ SG_ 2416373360 S2P_Cfg5_ModuleParal_Num_48 "当前SBMU模组并联数量？确认内容 wgw:PAL_CSC_COUNT固定为1";
CM_ SG_ 2416373360 S2P_Cfg5_CellSeries_Num_48 "电柜串联电芯数   CELL_NO *NUM_OF_CSC";
CM_ SG_ 2416373360 S2P_Cfg5_Temps_Num_48 "当前SBMU管理的环境温度采样点数目";
CM_ SG_ 2416373360 S2P_Cfg5_CSCs_Num_48 "当前SBMU管理的CSC数目";
CM_ SG_ 2416373360 S2P_Cfg5_Utank_Norminal_48 "分柜标称电压";
CM_ SG_ 2416373360 S2P_Cfg5_CSCType_48 "CSC类型";
CM_ SG_ 2416373361 S2P_Cfg5_SBMU_Add_49 "SBMU的地址";
CM_ SG_ 2416373361 S2P_Cfg5_ModuleParal_Num_49 "当前SBMU模组并联数量？确认内容 wgw:PAL_CSC_COUNT固定为1";
CM_ SG_ 2416373361 S2P_Cfg5_CellSeries_Num_49 "电柜串联电芯数   CELL_NO *NUM_OF_CSC";
CM_ SG_ 2416373361 S2P_Cfg5_Temps_Num_49 "当前SBMU管理的环境温度采样点数目";
CM_ SG_ 2416373361 S2P_Cfg5_CSCs_Num_49 "当前SBMU管理的CSC数目";
CM_ SG_ 2416373361 S2P_Cfg5_Utank_Norminal_49 "分柜标称电压";
CM_ SG_ 2416373361 S2P_Cfg5_CSCType_49 "CSC类型";
CM_ SG_ 2416373362 S2P_Cfg5_SBMU_Add_50 "SBMU的地址";
CM_ SG_ 2416373362 S2P_Cfg5_ModuleParal_Num_50 "当前SBMU模组并联数量？确认内容 wgw:PAL_CSC_COUNT固定为1";
CM_ SG_ 2416373362 S2P_Cfg5_CellSeries_Num_50 "电柜串联电芯数   CELL_NO *NUM_OF_CSC";
CM_ SG_ 2416373362 S2P_Cfg5_Temps_Num_50 "当前SBMU管理的环境温度采样点数目";
CM_ SG_ 2416373362 S2P_Cfg5_CSCs_Num_50 "当前SBMU管理的CSC数目";
CM_ SG_ 2416373362 S2P_Cfg5_Utank_Norminal_50 "分柜标称电压";
CM_ SG_ 2416373362 S2P_Cfg5_CSCType_50 "CSC类型";
CM_ SG_ 2416373363 S2P_Cfg5_SBMU_Add_51 "SBMU的地址";
CM_ SG_ 2416373363 S2P_Cfg5_ModuleParal_Num_51 "当前SBMU模组并联数量？确认内容 wgw:PAL_CSC_COUNT固定为1";
CM_ SG_ 2416373363 S2P_Cfg5_CellSeries_Num_51 "电柜串联电芯数   CELL_NO *NUM_OF_CSC";
CM_ SG_ 2416373363 S2P_Cfg5_Temps_Num_51 "当前SBMU管理的环境温度采样点数目";
CM_ SG_ 2416373363 S2P_Cfg5_CSCs_Num_51 "当前SBMU管理的CSC数目";
CM_ SG_ 2416373363 S2P_Cfg5_Utank_Norminal_51 "分柜标称电压";
CM_ SG_ 2416373363 S2P_Cfg5_CSCType_51 "CSC类型";
CM_ SG_ 2416373364 S2P_Cfg5_SBMU_Add_52 "SBMU的地址";
CM_ SG_ 2416373364 S2P_Cfg5_ModuleParal_Num_52 "当前SBMU模组并联数量？确认内容 wgw:PAL_CSC_COUNT固定为1";
CM_ SG_ 2416373364 S2P_Cfg5_CellSeries_Num_52 "电柜串联电芯数   CELL_NO *NUM_OF_CSC";
CM_ SG_ 2416373364 S2P_Cfg5_Temps_Num_52 "当前SBMU管理的环境温度采样点数目";
CM_ SG_ 2416373364 S2P_Cfg5_CSCs_Num_52 "当前SBMU管理的CSC数目";
CM_ SG_ 2416373364 S2P_Cfg5_Utank_Norminal_52 "分柜标称电压";
CM_ SG_ 2416373364 S2P_Cfg5_CSCType_52 "CSC类型";
CM_ SG_ 2416373365 S2P_Cfg5_SBMU_Add_53 "SBMU的地址";
CM_ SG_ 2416373365 S2P_Cfg5_ModuleParal_Num_53 "当前SBMU模组并联数量？确认内容 wgw:PAL_CSC_COUNT固定为1";
CM_ SG_ 2416373365 S2P_Cfg5_CellSeries_Num_53 "电柜串联电芯数   CELL_NO *NUM_OF_CSC";
CM_ SG_ 2416373365 S2P_Cfg5_Temps_Num_53 "当前SBMU管理的环境温度采样点数目";
CM_ SG_ 2416373365 S2P_Cfg5_CSCs_Num_53 "当前SBMU管理的CSC数目";
CM_ SG_ 2416373365 S2P_Cfg5_Utank_Norminal_53 "分柜标称电压";
CM_ SG_ 2416373365 S2P_Cfg5_CSCType_53 "CSC类型";
CM_ SG_ 2416373366 S2P_Cfg5_SBMU_Add_54 "SBMU的地址";
CM_ SG_ 2416373366 S2P_Cfg5_ModuleParal_Num_54 "当前SBMU模组并联数量？确认内容 wgw:PAL_CSC_COUNT固定为1";
CM_ SG_ 2416373366 S2P_Cfg5_CellSeries_Num_54 "电柜串联电芯数   CELL_NO *NUM_OF_CSC";
CM_ SG_ 2416373366 S2P_Cfg5_Temps_Num_54 "当前SBMU管理的环境温度采样点数目";
CM_ SG_ 2416373366 S2P_Cfg5_CSCs_Num_54 "当前SBMU管理的CSC数目";
CM_ SG_ 2416373366 S2P_Cfg5_Utank_Norminal_54 "分柜标称电压";
CM_ SG_ 2416373366 S2P_Cfg5_CSCType_54 "CSC类型";
CM_ SG_ 2416373367 S2P_Cfg5_SBMU_Add_55 "SBMU的地址";
CM_ SG_ 2416373367 S2P_Cfg5_ModuleParal_Num_55 "当前SBMU模组并联数量？确认内容 wgw:PAL_CSC_COUNT固定为1";
CM_ SG_ 2416373367 S2P_Cfg5_CellSeries_Num_55 "电柜串联电芯数   CELL_NO *NUM_OF_CSC";
CM_ SG_ 2416373367 S2P_Cfg5_Temps_Num_55 "当前SBMU管理的环境温度采样点数目";
CM_ SG_ 2416373367 S2P_Cfg5_CSCs_Num_55 "当前SBMU管理的CSC数目";
CM_ SG_ 2416373367 S2P_Cfg5_Utank_Norminal_55 "分柜标称电压";
CM_ SG_ 2416373367 S2P_Cfg5_CSCType_55 "CSC类型";
CM_ SG_ 2416373368 S2P_Cfg5_SBMU_Add_56 "SBMU的地址";
CM_ SG_ 2416373368 S2P_Cfg5_ModuleParal_Num_56 "当前SBMU模组并联数量？确认内容 wgw:PAL_CSC_COUNT固定为1";
CM_ SG_ 2416373368 S2P_Cfg5_CellSeries_Num_56 "电柜串联电芯数   CELL_NO *NUM_OF_CSC";
CM_ SG_ 2416373368 S2P_Cfg5_Temps_Num_56 "当前SBMU管理的环境温度采样点数目";
CM_ SG_ 2416373368 S2P_Cfg5_CSCs_Num_56 "当前SBMU管理的CSC数目";
CM_ SG_ 2416373368 S2P_Cfg5_Utank_Norminal_56 "分柜标称电压";
CM_ SG_ 2416373368 S2P_Cfg5_CSCType_56 "CSC类型";
CM_ SG_ 2416373369 S2P_Cfg5_SBMU_Add_57 "SBMU的地址";
CM_ SG_ 2416373369 S2P_Cfg5_ModuleParal_Num_57 "当前SBMU模组并联数量？确认内容 wgw:PAL_CSC_COUNT固定为1";
CM_ SG_ 2416373369 S2P_Cfg5_CellSeries_Num_57 "电柜串联电芯数   CELL_NO *NUM_OF_CSC";
CM_ SG_ 2416373369 S2P_Cfg5_Temps_Num_57 "当前SBMU管理的环境温度采样点数目";
CM_ SG_ 2416373369 S2P_Cfg5_CSCs_Num_57 "当前SBMU管理的CSC数目";
CM_ SG_ 2416373369 S2P_Cfg5_Utank_Norminal_57 "分柜标称电压";
CM_ SG_ 2416373369 S2P_Cfg5_CSCType_57 "CSC类型";
CM_ SG_ 2416373370 S2P_Cfg5_SBMU_Add_58 "SBMU的地址";
CM_ SG_ 2416373370 S2P_Cfg5_ModuleParal_Num_58 "当前SBMU模组并联数量？确认内容 wgw:PAL_CSC_COUNT固定为1";
CM_ SG_ 2416373370 S2P_Cfg5_CellSeries_Num_58 "电柜串联电芯数   CELL_NO *NUM_OF_CSC";
CM_ SG_ 2416373370 S2P_Cfg5_Temps_Num_58 "当前SBMU管理的环境温度采样点数目";
CM_ SG_ 2416373370 S2P_Cfg5_CSCs_Num_58 "当前SBMU管理的CSC数目";
CM_ SG_ 2416373370 S2P_Cfg5_Utank_Norminal_58 "分柜标称电压";
CM_ SG_ 2416373370 S2P_Cfg5_CSCType_58 "CSC类型";
CM_ SG_ 2416373371 S2P_Cfg5_SBMU_Add_59 "SBMU的地址";
CM_ SG_ 2416373371 S2P_Cfg5_ModuleParal_Num_59 "当前SBMU模组并联数量？确认内容 wgw:PAL_CSC_COUNT固定为1";
CM_ SG_ 2416373371 S2P_Cfg5_CellSeries_Num_59 "电柜串联电芯数   CELL_NO *NUM_OF_CSC";
CM_ SG_ 2416373371 S2P_Cfg5_Temps_Num_59 "当前SBMU管理的环境温度采样点数目";
CM_ SG_ 2416373371 S2P_Cfg5_CSCs_Num_59 "当前SBMU管理的CSC数目";
CM_ SG_ 2416373371 S2P_Cfg5_Utank_Norminal_59 "分柜标称电压";
CM_ SG_ 2416373371 S2P_Cfg5_CSCType_59 "CSC类型";
CM_ SG_ 2416373372 S2P_Cfg5_SBMU_Add_60 "SBMU的地址";
CM_ SG_ 2416373372 S2P_Cfg5_ModuleParal_Num_60 "当前SBMU模组并联数量？确认内容 wgw:PAL_CSC_COUNT固定为1";
CM_ SG_ 2416373372 S2P_Cfg5_CellSeries_Num_60 "电柜串联电芯数   CELL_NO *NUM_OF_CSC";
CM_ SG_ 2416373372 S2P_Cfg5_Temps_Num_60 "当前SBMU管理的环境温度采样点数目";
CM_ SG_ 2416373372 S2P_Cfg5_CSCs_Num_60 "当前SBMU管理的CSC数目";
CM_ SG_ 2416373372 S2P_Cfg5_Utank_Norminal_60 "分柜标称电压";
CM_ SG_ 2416373372 S2P_Cfg5_CSCType_60 "CSC类型";
CM_ SG_ 2416373373 S2P_Cfg5_SBMU_Add_61 "SBMU的地址";
CM_ SG_ 2416373373 S2P_Cfg5_ModuleParal_Num_61 "当前SBMU模组并联数量？确认内容 wgw:PAL_CSC_COUNT固定为1";
CM_ SG_ 2416373373 S2P_Cfg5_CellSeries_Num_61 "电柜串联电芯数   CELL_NO *NUM_OF_CSC";
CM_ SG_ 2416373373 S2P_Cfg5_Temps_Num_61 "当前SBMU管理的环境温度采样点数目";
CM_ SG_ 2416373373 S2P_Cfg5_CSCs_Num_61 "当前SBMU管理的CSC数目";
CM_ SG_ 2416373373 S2P_Cfg5_Utank_Norminal_61 "分柜标称电压";
CM_ SG_ 2416373373 S2P_Cfg5_CSCType_61 "CSC类型";
CM_ SG_ 2416373374 S2P_Cfg5_SBMU_Add_62 "SBMU的地址";
CM_ SG_ 2416373374 S2P_Cfg5_ModuleParal_Num_62 "当前SBMU模组并联数量？确认内容 wgw:PAL_CSC_COUNT固定为1";
CM_ SG_ 2416373374 S2P_Cfg5_CellSeries_Num_62 "电柜串联电芯数   CELL_NO *NUM_OF_CSC";
CM_ SG_ 2416373374 S2P_Cfg5_Temps_Num_62 "当前SBMU管理的环境温度采样点数目";
CM_ SG_ 2416373374 S2P_Cfg5_CSCs_Num_62 "当前SBMU管理的CSC数目";
CM_ SG_ 2416373374 S2P_Cfg5_Utank_Norminal_62 "分柜标称电压";
CM_ SG_ 2416373374 S2P_Cfg5_CSCType_62 "CSC类型";
CM_ SG_ 2416373375 S2P_Cfg5_SBMU_Add_63 "SBMU的地址";
CM_ SG_ 2416373375 S2P_Cfg5_ModuleParal_Num_63 "当前SBMU模组并联数量？确认内容 wgw:PAL_CSC_COUNT固定为1";
CM_ SG_ 2416373375 S2P_Cfg5_CellSeries_Num_63 "电柜串联电芯数   CELL_NO *NUM_OF_CSC";
CM_ SG_ 2416373375 S2P_Cfg5_Temps_Num_63 "当前SBMU管理的环境温度采样点数目";
CM_ SG_ 2416373375 S2P_Cfg5_CSCs_Num_63 "当前SBMU管理的CSC数目";
CM_ SG_ 2416373375 S2P_Cfg5_Utank_Norminal_63 "分柜标称电压";
CM_ SG_ 2416373375 S2P_Cfg5_CSCType_63 "CSC类型";
CM_ SG_ 2416438849 S2P_Cfg6_Ucell_Norminal_01 "单体标称电压";
CM_ SG_ 2416438849 S2P_Cfg6_Ccell_Norminal_01 "单体标称容量";
CM_ SG_ 2416438850 S2P_Cfg6_Ucell_Norminal_02 "单体标称电压";
CM_ SG_ 2416438850 S2P_Cfg6_Ccell_Norminal_02 "单体标称容量";
CM_ SG_ 2416438851 S2P_Cfg6_Ucell_Norminal_03 "单体标称电压";
CM_ SG_ 2416438851 S2P_Cfg6_Ccell_Norminal_03 "单体标称容量";
CM_ SG_ 2416438852 S2P_Cfg6_Ucell_Norminal_04 "单体标称电压";
CM_ SG_ 2416438852 S2P_Cfg6_Ccell_Norminal_04 "单体标称容量";
CM_ SG_ 2416438853 S2P_Cfg6_Ucell_Norminal_05 "单体标称电压";
CM_ SG_ 2416438853 S2P_Cfg6_Ccell_Norminal_05 "单体标称容量";
CM_ SG_ 2416438854 S2P_Cfg6_Ucell_Norminal_06 "单体标称电压";
CM_ SG_ 2416438854 S2P_Cfg6_Ccell_Norminal_06 "单体标称容量";
CM_ SG_ 2416438855 S2P_Cfg6_Ucell_Norminal_07 "单体标称电压";
CM_ SG_ 2416438855 S2P_Cfg6_Ccell_Norminal_07 "单体标称容量";
CM_ SG_ 2416438856 S2P_Cfg6_Ucell_Norminal_08 "单体标称电压";
CM_ SG_ 2416438856 S2P_Cfg6_Ccell_Norminal_08 "单体标称容量";
CM_ SG_ 2416438857 S2P_Cfg6_Ucell_Norminal_09 "单体标称电压";
CM_ SG_ 2416438857 S2P_Cfg6_Ccell_Norminal_09 "单体标称容量";
CM_ SG_ 2416438858 S2P_Cfg6_Ucell_Norminal_10 "单体标称电压";
CM_ SG_ 2416438858 S2P_Cfg6_Ccell_Norminal_10 "单体标称容量";
CM_ SG_ 2416438859 S2P_Cfg6_Ucell_Norminal_11 "单体标称电压";
CM_ SG_ 2416438859 S2P_Cfg6_Ccell_Norminal_11 "单体标称容量";
CM_ SG_ 2416438860 S2P_Cfg6_Ucell_Norminal_12 "单体标称电压";
CM_ SG_ 2416438860 S2P_Cfg6_Ccell_Norminal_12 "单体标称容量";
CM_ SG_ 2416438861 S2P_Cfg6_Ucell_Norminal_13 "单体标称电压";
CM_ SG_ 2416438861 S2P_Cfg6_Ccell_Norminal_13 "单体标称容量";
CM_ SG_ 2416438862 S2P_Cfg6_Ucell_Norminal_14 "单体标称电压";
CM_ SG_ 2416438862 S2P_Cfg6_Ccell_Norminal_14 "单体标称容量";
CM_ SG_ 2416438863 S2P_Cfg6_Ucell_Norminal_15 "单体标称电压";
CM_ SG_ 2416438863 S2P_Cfg6_Ccell_Norminal_15 "单体标称容量";
CM_ SG_ 2416438864 S2P_Cfg6_Ucell_Norminal_16 "单体标称电压";
CM_ SG_ 2416438864 S2P_Cfg6_Ccell_Norminal_16 "单体标称容量";
CM_ SG_ 2416438865 S2P_Cfg6_Ucell_Norminal_17 "单体标称电压";
CM_ SG_ 2416438865 S2P_Cfg6_Ccell_Norminal_17 "单体标称容量";
CM_ SG_ 2416438866 S2P_Cfg6_Ucell_Norminal_18 "单体标称电压";
CM_ SG_ 2416438866 S2P_Cfg6_Ccell_Norminal_18 "单体标称容量";
CM_ SG_ 2416438867 S2P_Cfg6_Ucell_Norminal_19 "单体标称电压";
CM_ SG_ 2416438867 S2P_Cfg6_Ccell_Norminal_19 "单体标称容量";
CM_ SG_ 2416438868 S2P_Cfg6_Ucell_Norminal_20 "单体标称电压";
CM_ SG_ 2416438868 S2P_Cfg6_Ccell_Norminal_20 "单体标称容量";
CM_ SG_ 2416438869 S2P_Cfg6_Ucell_Norminal_21 "单体标称电压";
CM_ SG_ 2416438869 S2P_Cfg6_Ccell_Norminal_21 "单体标称容量";
CM_ SG_ 2416438870 S2P_Cfg6_Ucell_Norminal_22 "单体标称电压";
CM_ SG_ 2416438870 S2P_Cfg6_Ccell_Norminal_22 "单体标称容量";
CM_ SG_ 2416438871 S2P_Cfg6_Ucell_Norminal_23 "单体标称电压";
CM_ SG_ 2416438871 S2P_Cfg6_Ccell_Norminal_23 "单体标称容量";
CM_ SG_ 2416438872 S2P_Cfg6_Ucell_Norminal_24 "单体标称电压";
CM_ SG_ 2416438872 S2P_Cfg6_Ccell_Norminal_24 "单体标称容量";
CM_ SG_ 2416438873 S2P_Cfg6_Ucell_Norminal_25 "单体标称电压";
CM_ SG_ 2416438873 S2P_Cfg6_Ccell_Norminal_25 "单体标称容量";
CM_ SG_ 2416438874 S2P_Cfg6_Ucell_Norminal_26 "单体标称电压";
CM_ SG_ 2416438874 S2P_Cfg6_Ccell_Norminal_26 "单体标称容量";
CM_ SG_ 2416438875 S2P_Cfg6_Ucell_Norminal_27 "单体标称电压";
CM_ SG_ 2416438875 S2P_Cfg6_Ccell_Norminal_27 "单体标称容量";
CM_ SG_ 2416438876 S2P_Cfg6_Ucell_Norminal_28 "单体标称电压";
CM_ SG_ 2416438876 S2P_Cfg6_Ccell_Norminal_28 "单体标称容量";
CM_ SG_ 2416438877 S2P_Cfg6_Ucell_Norminal_29 "单体标称电压";
CM_ SG_ 2416438877 S2P_Cfg6_Ccell_Norminal_29 "单体标称容量";
CM_ SG_ 2416438878 S2P_Cfg6_Ucell_Norminal_30 "单体标称电压";
CM_ SG_ 2416438878 S2P_Cfg6_Ccell_Norminal_30 "单体标称容量";
CM_ SG_ 2416438879 S2P_Cfg6_Ucell_Norminal_31 "单体标称电压";
CM_ SG_ 2416438879 S2P_Cfg6_Ccell_Norminal_31 "单体标称容量";
CM_ SG_ 2416438880 S2P_Cfg6_Ucell_Norminal_32 "单体标称电压";
CM_ SG_ 2416438880 S2P_Cfg6_Ccell_Norminal_32 "单体标称容量";
CM_ SG_ 2416438881 S2P_Cfg6_Ucell_Norminal_33 "单体标称电压";
CM_ SG_ 2416438881 S2P_Cfg6_Ccell_Norminal_33 "单体标称容量";
CM_ SG_ 2416438882 S2P_Cfg6_Ucell_Norminal_34 "单体标称电压";
CM_ SG_ 2416438882 S2P_Cfg6_Ccell_Norminal_34 "单体标称容量";
CM_ SG_ 2416438883 S2P_Cfg6_Ucell_Norminal_35 "单体标称电压";
CM_ SG_ 2416438883 S2P_Cfg6_Ccell_Norminal_35 "单体标称容量";
CM_ SG_ 2416438884 S2P_Cfg6_Ucell_Norminal_36 "单体标称电压";
CM_ SG_ 2416438884 S2P_Cfg6_Ccell_Norminal_36 "单体标称容量";
CM_ SG_ 2416438885 S2P_Cfg6_Ucell_Norminal_37 "单体标称电压";
CM_ SG_ 2416438885 S2P_Cfg6_Ccell_Norminal_37 "单体标称容量";
CM_ SG_ 2416438886 S2P_Cfg6_Ucell_Norminal_38 "单体标称电压";
CM_ SG_ 2416438886 S2P_Cfg6_Ccell_Norminal_38 "单体标称容量";
CM_ SG_ 2416438887 S2P_Cfg6_Ucell_Norminal_39 "单体标称电压";
CM_ SG_ 2416438887 S2P_Cfg6_Ccell_Norminal_39 "单体标称容量";
CM_ SG_ 2416438888 S2P_Cfg6_Ucell_Norminal_40 "单体标称电压";
CM_ SG_ 2416438888 S2P_Cfg6_Ccell_Norminal_40 "单体标称容量";
CM_ SG_ 2416438889 S2P_Cfg6_Ucell_Norminal_41 "单体标称电压";
CM_ SG_ 2416438889 S2P_Cfg6_Ccell_Norminal_41 "单体标称容量";
CM_ SG_ 2416438890 S2P_Cfg6_Ucell_Norminal_42 "单体标称电压";
CM_ SG_ 2416438890 S2P_Cfg6_Ccell_Norminal_42 "单体标称容量";
CM_ SG_ 2416438891 S2P_Cfg6_Ucell_Norminal_43 "单体标称电压";
CM_ SG_ 2416438891 S2P_Cfg6_Ccell_Norminal_43 "单体标称容量";
CM_ SG_ 2416438892 S2P_Cfg6_Ucell_Norminal_44 "单体标称电压";
CM_ SG_ 2416438892 S2P_Cfg6_Ccell_Norminal_44 "单体标称容量";
CM_ SG_ 2416438893 S2P_Cfg6_Ucell_Norminal_45 "单体标称电压";
CM_ SG_ 2416438893 S2P_Cfg6_Ccell_Norminal_45 "单体标称容量";
CM_ SG_ 2416438894 S2P_Cfg6_Ucell_Norminal_46 "单体标称电压";
CM_ SG_ 2416438894 S2P_Cfg6_Ccell_Norminal_46 "单体标称容量";
CM_ SG_ 2416438895 S2P_Cfg6_Ucell_Norminal_47 "单体标称电压";
CM_ SG_ 2416438895 S2P_Cfg6_Ccell_Norminal_47 "单体标称容量";
CM_ SG_ 2416438896 S2P_Cfg6_Ucell_Norminal_48 "单体标称电压";
CM_ SG_ 2416438896 S2P_Cfg6_Ccell_Norminal_48 "单体标称容量";
CM_ SG_ 2416438897 S2P_Cfg6_Ucell_Norminal_49 "单体标称电压";
CM_ SG_ 2416438897 S2P_Cfg6_Ccell_Norminal_49 "单体标称容量";
CM_ SG_ 2416438898 S2P_Cfg6_Ucell_Norminal_50 "单体标称电压";
CM_ SG_ 2416438898 S2P_Cfg6_Ccell_Norminal_50 "单体标称容量";
CM_ SG_ 2416438899 S2P_Cfg6_Ucell_Norminal_51 "单体标称电压";
CM_ SG_ 2416438899 S2P_Cfg6_Ccell_Norminal_51 "单体标称容量";
CM_ SG_ 2416438900 S2P_Cfg6_Ucell_Norminal_52 "单体标称电压";
CM_ SG_ 2416438900 S2P_Cfg6_Ccell_Norminal_52 "单体标称容量";
CM_ SG_ 2416438901 S2P_Cfg6_Ucell_Norminal_53 "单体标称电压";
CM_ SG_ 2416438901 S2P_Cfg6_Ccell_Norminal_53 "单体标称容量";
CM_ SG_ 2416438902 S2P_Cfg6_Ucell_Norminal_54 "单体标称电压";
CM_ SG_ 2416438902 S2P_Cfg6_Ccell_Norminal_54 "单体标称容量";
CM_ SG_ 2416438903 S2P_Cfg6_Ucell_Norminal_55 "单体标称电压";
CM_ SG_ 2416438903 S2P_Cfg6_Ccell_Norminal_55 "单体标称容量";
CM_ SG_ 2416438904 S2P_Cfg6_Ucell_Norminal_56 "单体标称电压";
CM_ SG_ 2416438904 S2P_Cfg6_Ccell_Norminal_56 "单体标称容量";
CM_ SG_ 2416438905 S2P_Cfg6_Ucell_Norminal_57 "单体标称电压";
CM_ SG_ 2416438905 S2P_Cfg6_Ccell_Norminal_57 "单体标称容量";
CM_ SG_ 2416438906 S2P_Cfg6_Ucell_Norminal_58 "单体标称电压";
CM_ SG_ 2416438906 S2P_Cfg6_Ccell_Norminal_58 "单体标称容量";
CM_ SG_ 2416438907 S2P_Cfg6_Ucell_Norminal_59 "单体标称电压";
CM_ SG_ 2416438907 S2P_Cfg6_Ccell_Norminal_59 "单体标称容量";
CM_ SG_ 2416438908 S2P_Cfg6_Ucell_Norminal_60 "单体标称电压";
CM_ SG_ 2416438908 S2P_Cfg6_Ccell_Norminal_60 "单体标称容量";
CM_ SG_ 2416438909 S2P_Cfg6_Ucell_Norminal_61 "单体标称电压";
CM_ SG_ 2416438909 S2P_Cfg6_Ccell_Norminal_61 "单体标称容量";
CM_ SG_ 2416438910 S2P_Cfg6_Ucell_Norminal_62 "单体标称电压";
CM_ SG_ 2416438910 S2P_Cfg6_Ccell_Norminal_62 "单体标称容量";
CM_ SG_ 2416438911 S2P_Cfg6_Ucell_Norminal_63 "单体标称电压";
CM_ SG_ 2416438911 S2P_Cfg6_Ccell_Norminal_63 "单体标称容量";
CM_ SG_ 2416504385 S2P_Cfg7_CSCCellSeries_Num_01 "单个CSC中电芯串联的数目";
CM_ SG_ 2416504385 S2P_Cfg7_CSCCellParal_Num_01 "单个CSC中电芯并联的数目";
CM_ SG_ 2416504385 S2P_Cfg7_CSCTempsNum_01 "单个CSC中温度检测点的数目";
CM_ SG_ 2416504385 S2P_Cfg7_CSCCellTempsNum_01 "单个CSC中单芯温度检测点的数目(剔除电极温度)";
CM_ SG_ 2416504386 S2P_Cfg7_CSCCellSeries_Num_02 "单个CSC中电芯串联的数目";
CM_ SG_ 2416504386 S2P_Cfg7_CSCCellParal_Num_02 "单个CSC中电芯并联的数目";
CM_ SG_ 2416504386 S2P_Cfg7_CSCTempsNum_02 "单个CSC中温度检测点的数目";
CM_ SG_ 2416504386 S2P_Cfg7_CSCCellTempsNum_02 "单个CSC中单芯温度检测点的数目(剔除电极温度)";
CM_ SG_ 2416504387 S2P_Cfg7_CSCCellSeries_Num_03 "单个CSC中电芯串联的数目";
CM_ SG_ 2416504387 S2P_Cfg7_CSCCellParal_Num_03 "单个CSC中电芯并联的数目";
CM_ SG_ 2416504387 S2P_Cfg7_CSCTempsNum_03 "单个CSC中温度检测点的数目";
CM_ SG_ 2416504387 S2P_Cfg7_CSCCellTempsNum_03 "单个CSC中单芯温度检测点的数目(剔除电极温度)";
CM_ SG_ 2416504388 S2P_Cfg7_CSCCellSeries_Num_04 "单个CSC中电芯串联的数目";
CM_ SG_ 2416504388 S2P_Cfg7_CSCCellParal_Num_04 "单个CSC中电芯并联的数目";
CM_ SG_ 2416504388 S2P_Cfg7_CSCTempsNum_04 "单个CSC中温度检测点的数目";
CM_ SG_ 2416504388 S2P_Cfg7_CSCCellTempsNum_04 "单个CSC中单芯温度检测点的数目(剔除电极温度)";
CM_ SG_ 2416504389 S2P_Cfg7_CSCCellSeries_Num_05 "单个CSC中电芯串联的数目";
CM_ SG_ 2416504389 S2P_Cfg7_CSCCellParal_Num_05 "单个CSC中电芯并联的数目";
CM_ SG_ 2416504389 S2P_Cfg7_CSCTempsNum_05 "单个CSC中温度检测点的数目";
CM_ SG_ 2416504389 S2P_Cfg7_CSCCellTempsNum_05 "单个CSC中单芯温度检测点的数目(剔除电极温度)";
CM_ SG_ 2416504390 S2P_Cfg7_CSCCellSeries_Num_06 "单个CSC中电芯串联的数目";
CM_ SG_ 2416504390 S2P_Cfg7_CSCCellParal_Num_06 "单个CSC中电芯并联的数目";
CM_ SG_ 2416504390 S2P_Cfg7_CSCTempsNum_06 "单个CSC中温度检测点的数目";
CM_ SG_ 2416504390 S2P_Cfg7_CSCCellTempsNum_06 "单个CSC中单芯温度检测点的数目(剔除电极温度)";
CM_ SG_ 2416504391 S2P_Cfg7_CSCCellSeries_Num_07 "单个CSC中电芯串联的数目";
CM_ SG_ 2416504391 S2P_Cfg7_CSCCellParal_Num_07 "单个CSC中电芯并联的数目";
CM_ SG_ 2416504391 S2P_Cfg7_CSCTempsNum_07 "单个CSC中温度检测点的数目";
CM_ SG_ 2416504391 S2P_Cfg7_CSCCellTempsNum_07 "单个CSC中单芯温度检测点的数目(剔除电极温度)";
CM_ SG_ 2416504392 S2P_Cfg7_CSCCellSeries_Num_08 "单个CSC中电芯串联的数目";
CM_ SG_ 2416504392 S2P_Cfg7_CSCCellParal_Num_08 "单个CSC中电芯并联的数目";
CM_ SG_ 2416504392 S2P_Cfg7_CSCTempsNum_08 "单个CSC中温度检测点的数目";
CM_ SG_ 2416504392 S2P_Cfg7_CSCCellTempsNum_08 "单个CSC中单芯温度检测点的数目(剔除电极温度)";
CM_ SG_ 2416504393 S2P_Cfg7_CSCCellSeries_Num_09 "单个CSC中电芯串联的数目";
CM_ SG_ 2416504393 S2P_Cfg7_CSCCellParal_Num_09 "单个CSC中电芯并联的数目";
CM_ SG_ 2416504393 S2P_Cfg7_CSCTempsNum_09 "单个CSC中温度检测点的数目";
CM_ SG_ 2416504393 S2P_Cfg7_CSCCellTempsNum_09 "单个CSC中单芯温度检测点的数目(剔除电极温度)";
CM_ SG_ 2416504394 S2P_Cfg7_CSCCellSeries_Num_10 "单个CSC中电芯串联的数目";
CM_ SG_ 2416504394 S2P_Cfg7_CSCCellParal_Num_10 "单个CSC中电芯并联的数目";
CM_ SG_ 2416504394 S2P_Cfg7_CSCTempsNum_10 "单个CSC中温度检测点的数目";
CM_ SG_ 2416504394 S2P_Cfg7_CSCCellTempsNum_10 "单个CSC中单芯温度检测点的数目(剔除电极温度)";
CM_ SG_ 2416504395 S2P_Cfg7_CSCCellSeries_Num_11 "单个CSC中电芯串联的数目";
CM_ SG_ 2416504395 S2P_Cfg7_CSCCellParal_Num_11 "单个CSC中电芯并联的数目";
CM_ SG_ 2416504395 S2P_Cfg7_CSCTempsNum_11 "单个CSC中温度检测点的数目";
CM_ SG_ 2416504395 S2P_Cfg7_CSCCellTempsNum_11 "单个CSC中单芯温度检测点的数目(剔除电极温度)";
CM_ SG_ 2416504396 S2P_Cfg7_CSCCellSeries_Num_12 "单个CSC中电芯串联的数目";
CM_ SG_ 2416504396 S2P_Cfg7_CSCCellParal_Num_12 "单个CSC中电芯并联的数目";
CM_ SG_ 2416504396 S2P_Cfg7_CSCTempsNum_12 "单个CSC中温度检测点的数目";
CM_ SG_ 2416504396 S2P_Cfg7_CSCCellTempsNum_12 "单个CSC中单芯温度检测点的数目(剔除电极温度)";
CM_ SG_ 2416504397 S2P_Cfg7_CSCCellSeries_Num_13 "单个CSC中电芯串联的数目";
CM_ SG_ 2416504397 S2P_Cfg7_CSCCellParal_Num_13 "单个CSC中电芯并联的数目";
CM_ SG_ 2416504397 S2P_Cfg7_CSCTempsNum_13 "单个CSC中温度检测点的数目";
CM_ SG_ 2416504397 S2P_Cfg7_CSCCellTempsNum_13 "单个CSC中单芯温度检测点的数目(剔除电极温度)";
CM_ SG_ 2416504398 S2P_Cfg7_CSCCellSeries_Num_14 "单个CSC中电芯串联的数目";
CM_ SG_ 2416504398 S2P_Cfg7_CSCCellParal_Num_14 "单个CSC中电芯并联的数目";
CM_ SG_ 2416504398 S2P_Cfg7_CSCTempsNum_14 "单个CSC中温度检测点的数目";
CM_ SG_ 2416504398 S2P_Cfg7_CSCCellTempsNum_14 "单个CSC中单芯温度检测点的数目(剔除电极温度)";
CM_ SG_ 2416504399 S2P_Cfg7_CSCCellSeries_Num_15 "单个CSC中电芯串联的数目";
CM_ SG_ 2416504399 S2P_Cfg7_CSCCellParal_Num_15 "单个CSC中电芯并联的数目";
CM_ SG_ 2416504399 S2P_Cfg7_CSCTempsNum_15 "单个CSC中温度检测点的数目";
CM_ SG_ 2416504399 S2P_Cfg7_CSCCellTempsNum_15 "单个CSC中单芯温度检测点的数目(剔除电极温度)";
CM_ SG_ 2416504400 S2P_Cfg7_CSCCellSeries_Num_16 "单个CSC中电芯串联的数目";
CM_ SG_ 2416504400 S2P_Cfg7_CSCCellParal_Num_16 "单个CSC中电芯并联的数目";
CM_ SG_ 2416504400 S2P_Cfg7_CSCTempsNum_16 "单个CSC中温度检测点的数目";
CM_ SG_ 2416504400 S2P_Cfg7_CSCCellTempsNum_16 "单个CSC中单芯温度检测点的数目(剔除电极温度)";
CM_ SG_ 2416504401 S2P_Cfg7_CSCCellSeries_Num_17 "单个CSC中电芯串联的数目";
CM_ SG_ 2416504401 S2P_Cfg7_CSCCellParal_Num_17 "单个CSC中电芯并联的数目";
CM_ SG_ 2416504401 S2P_Cfg7_CSCTempsNum_17 "单个CSC中温度检测点的数目";
CM_ SG_ 2416504401 S2P_Cfg7_CSCCellTempsNum_17 "单个CSC中单芯温度检测点的数目(剔除电极温度)";
CM_ SG_ 2416504402 S2P_Cfg7_CSCCellSeries_Num_18 "单个CSC中电芯串联的数目";
CM_ SG_ 2416504402 S2P_Cfg7_CSCCellParal_Num_18 "单个CSC中电芯并联的数目";
CM_ SG_ 2416504402 S2P_Cfg7_CSCTempsNum_18 "单个CSC中温度检测点的数目";
CM_ SG_ 2416504402 S2P_Cfg7_CSCCellTempsNum_18 "单个CSC中单芯温度检测点的数目(剔除电极温度)";
CM_ SG_ 2416504403 S2P_Cfg7_CSCCellSeries_Num_19 "单个CSC中电芯串联的数目";
CM_ SG_ 2416504403 S2P_Cfg7_CSCCellParal_Num_19 "单个CSC中电芯并联的数目";
CM_ SG_ 2416504403 S2P_Cfg7_CSCTempsNum_19 "单个CSC中温度检测点的数目";
CM_ SG_ 2416504403 S2P_Cfg7_CSCCellTempsNum_19 "单个CSC中单芯温度检测点的数目(剔除电极温度)";
CM_ SG_ 2416504404 S2P_Cfg7_CSCCellSeries_Num_20 "单个CSC中电芯串联的数目";
CM_ SG_ 2416504404 S2P_Cfg7_CSCCellParal_Num_20 "单个CSC中电芯并联的数目";
CM_ SG_ 2416504404 S2P_Cfg7_CSCTempsNum_20 "单个CSC中温度检测点的数目";
CM_ SG_ 2416504404 S2P_Cfg7_CSCCellTempsNum_20 "单个CSC中单芯温度检测点的数目(剔除电极温度)";
CM_ SG_ 2416504405 S2P_Cfg7_CSCCellSeries_Num_21 "单个CSC中电芯串联的数目";
CM_ SG_ 2416504405 S2P_Cfg7_CSCCellParal_Num_21 "单个CSC中电芯并联的数目";
CM_ SG_ 2416504405 S2P_Cfg7_CSCTempsNum_21 "单个CSC中温度检测点的数目";
CM_ SG_ 2416504405 S2P_Cfg7_CSCCellTempsNum_21 "单个CSC中单芯温度检测点的数目(剔除电极温度)";
CM_ SG_ 2416504406 S2P_Cfg7_CSCCellSeries_Num_22 "单个CSC中电芯串联的数目";
CM_ SG_ 2416504406 S2P_Cfg7_CSCCellParal_Num_22 "单个CSC中电芯并联的数目";
CM_ SG_ 2416504406 S2P_Cfg7_CSCTempsNum_22 "单个CSC中温度检测点的数目";
CM_ SG_ 2416504406 S2P_Cfg7_CSCCellTempsNum_22 "单个CSC中单芯温度检测点的数目(剔除电极温度)";
CM_ SG_ 2416504407 S2P_Cfg7_CSCCellSeries_Num_23 "单个CSC中电芯串联的数目";
CM_ SG_ 2416504407 S2P_Cfg7_CSCCellParal_Num_23 "单个CSC中电芯并联的数目";
CM_ SG_ 2416504407 S2P_Cfg7_CSCTempsNum_23 "单个CSC中温度检测点的数目";
CM_ SG_ 2416504407 S2P_Cfg7_CSCCellTempsNum_23 "单个CSC中单芯温度检测点的数目(剔除电极温度)";
CM_ SG_ 2416504408 S2P_Cfg7_CSCCellSeries_Num_24 "单个CSC中电芯串联的数目";
CM_ SG_ 2416504408 S2P_Cfg7_CSCCellParal_Num_24 "单个CSC中电芯并联的数目";
CM_ SG_ 2416504408 S2P_Cfg7_CSCTempsNum_24 "单个CSC中温度检测点的数目";
CM_ SG_ 2416504408 S2P_Cfg7_CSCCellTempsNum_24 "单个CSC中单芯温度检测点的数目(剔除电极温度)";
CM_ SG_ 2416504409 S2P_Cfg7_CSCCellSeries_Num_25 "单个CSC中电芯串联的数目";
CM_ SG_ 2416504409 S2P_Cfg7_CSCCellParal_Num_25 "单个CSC中电芯并联的数目";
CM_ SG_ 2416504409 S2P_Cfg7_CSCTempsNum_25 "单个CSC中温度检测点的数目";
CM_ SG_ 2416504409 S2P_Cfg7_CSCCellTempsNum_25 "单个CSC中单芯温度检测点的数目(剔除电极温度)";
CM_ SG_ 2416504410 S2P_Cfg7_CSCCellSeries_Num_26 "单个CSC中电芯串联的数目";
CM_ SG_ 2416504410 S2P_Cfg7_CSCCellParal_Num_26 "单个CSC中电芯并联的数目";
CM_ SG_ 2416504410 S2P_Cfg7_CSCTempsNum_26 "单个CSC中温度检测点的数目";
CM_ SG_ 2416504410 S2P_Cfg7_CSCCellTempsNum_26 "单个CSC中单芯温度检测点的数目(剔除电极温度)";
CM_ SG_ 2416504411 S2P_Cfg7_CSCCellSeries_Num_27 "单个CSC中电芯串联的数目";
CM_ SG_ 2416504411 S2P_Cfg7_CSCCellParal_Num_27 "单个CSC中电芯并联的数目";
CM_ SG_ 2416504411 S2P_Cfg7_CSCTempsNum_27 "单个CSC中温度检测点的数目";
CM_ SG_ 2416504411 S2P_Cfg7_CSCCellTempsNum_27 "单个CSC中单芯温度检测点的数目(剔除电极温度)";
CM_ SG_ 2416504412 S2P_Cfg7_CSCCellSeries_Num_28 "单个CSC中电芯串联的数目";
CM_ SG_ 2416504412 S2P_Cfg7_CSCCellParal_Num_28 "单个CSC中电芯并联的数目";
CM_ SG_ 2416504412 S2P_Cfg7_CSCTempsNum_28 "单个CSC中温度检测点的数目";
CM_ SG_ 2416504412 S2P_Cfg7_CSCCellTempsNum_28 "单个CSC中单芯温度检测点的数目(剔除电极温度)";
CM_ SG_ 2416504413 S2P_Cfg7_CSCCellSeries_Num_29 "单个CSC中电芯串联的数目";
CM_ SG_ 2416504413 S2P_Cfg7_CSCCellParal_Num_29 "单个CSC中电芯并联的数目";
CM_ SG_ 2416504413 S2P_Cfg7_CSCTempsNum_29 "单个CSC中温度检测点的数目";
CM_ SG_ 2416504413 S2P_Cfg7_CSCCellTempsNum_29 "单个CSC中单芯温度检测点的数目(剔除电极温度)";
CM_ SG_ 2416504414 S2P_Cfg7_CSCCellSeries_Num_30 "单个CSC中电芯串联的数目";
CM_ SG_ 2416504414 S2P_Cfg7_CSCCellParal_Num_30 "单个CSC中电芯并联的数目";
CM_ SG_ 2416504414 S2P_Cfg7_CSCTempsNum_30 "单个CSC中温度检测点的数目";
CM_ SG_ 2416504414 S2P_Cfg7_CSCCellTempsNum_30 "单个CSC中单芯温度检测点的数目(剔除电极温度)";
CM_ SG_ 2416504415 S2P_Cfg7_CSCCellSeries_Num_31 "单个CSC中电芯串联的数目";
CM_ SG_ 2416504415 S2P_Cfg7_CSCCellParal_Num_31 "单个CSC中电芯并联的数目";
CM_ SG_ 2416504415 S2P_Cfg7_CSCTempsNum_31 "单个CSC中温度检测点的数目";
CM_ SG_ 2416504415 S2P_Cfg7_CSCCellTempsNum_31 "单个CSC中单芯温度检测点的数目(剔除电极温度)";
CM_ SG_ 2416504416 S2P_Cfg7_CSCCellSeries_Num_32 "单个CSC中电芯串联的数目";
CM_ SG_ 2416504416 S2P_Cfg7_CSCCellParal_Num_32 "单个CSC中电芯并联的数目";
CM_ SG_ 2416504416 S2P_Cfg7_CSCTempsNum_32 "单个CSC中温度检测点的数目";
CM_ SG_ 2416504416 S2P_Cfg7_CSCCellTempsNum_32 "单个CSC中单芯温度检测点的数目(剔除电极温度)";
CM_ SG_ 2416504417 S2P_Cfg7_CSCCellSeries_Num_33 "单个CSC中电芯串联的数目";
CM_ SG_ 2416504417 S2P_Cfg7_CSCCellParal_Num_33 "单个CSC中电芯并联的数目";
CM_ SG_ 2416504417 S2P_Cfg7_CSCTempsNum_33 "单个CSC中温度检测点的数目";
CM_ SG_ 2416504417 S2P_Cfg7_CSCCellTempsNum_33 "单个CSC中单芯温度检测点的数目(剔除电极温度)";
CM_ SG_ 2416504418 S2P_Cfg7_CSCCellSeries_Num_34 "单个CSC中电芯串联的数目";
CM_ SG_ 2416504418 S2P_Cfg7_CSCCellParal_Num_34 "单个CSC中电芯并联的数目";
CM_ SG_ 2416504418 S2P_Cfg7_CSCTempsNum_34 "单个CSC中温度检测点的数目";
CM_ SG_ 2416504418 S2P_Cfg7_CSCCellTempsNum_34 "单个CSC中单芯温度检测点的数目(剔除电极温度)";
CM_ SG_ 2416504419 S2P_Cfg7_CSCCellSeries_Num_35 "单个CSC中电芯串联的数目";
CM_ SG_ 2416504419 S2P_Cfg7_CSCCellParal_Num_35 "单个CSC中电芯并联的数目";
CM_ SG_ 2416504419 S2P_Cfg7_CSCTempsNum_35 "单个CSC中温度检测点的数目";
CM_ SG_ 2416504419 S2P_Cfg7_CSCCellTempsNum_35 "单个CSC中单芯温度检测点的数目(剔除电极温度)";
CM_ SG_ 2416504420 S2P_Cfg7_CSCCellSeries_Num_36 "单个CSC中电芯串联的数目";
CM_ SG_ 2416504420 S2P_Cfg7_CSCCellParal_Num_36 "单个CSC中电芯并联的数目";
CM_ SG_ 2416504420 S2P_Cfg7_CSCTempsNum_36 "单个CSC中温度检测点的数目";
CM_ SG_ 2416504420 S2P_Cfg7_CSCCellTempsNum_36 "单个CSC中单芯温度检测点的数目(剔除电极温度)";
CM_ SG_ 2416504421 S2P_Cfg7_CSCCellSeries_Num_37 "单个CSC中电芯串联的数目";
CM_ SG_ 2416504421 S2P_Cfg7_CSCCellParal_Num_37 "单个CSC中电芯并联的数目";
CM_ SG_ 2416504421 S2P_Cfg7_CSCTempsNum_37 "单个CSC中温度检测点的数目";
CM_ SG_ 2416504421 S2P_Cfg7_CSCCellTempsNum_37 "单个CSC中单芯温度检测点的数目(剔除电极温度)";
CM_ SG_ 2416504422 S2P_Cfg7_CSCCellSeries_Num_38 "单个CSC中电芯串联的数目";
CM_ SG_ 2416504422 S2P_Cfg7_CSCCellParal_Num_38 "单个CSC中电芯并联的数目";
CM_ SG_ 2416504422 S2P_Cfg7_CSCTempsNum_38 "单个CSC中温度检测点的数目";
CM_ SG_ 2416504422 S2P_Cfg7_CSCCellTempsNum_38 "单个CSC中单芯温度检测点的数目(剔除电极温度)";
CM_ SG_ 2416504423 S2P_Cfg7_CSCCellSeries_Num_39 "单个CSC中电芯串联的数目";
CM_ SG_ 2416504423 S2P_Cfg7_CSCCellParal_Num_39 "单个CSC中电芯并联的数目";
CM_ SG_ 2416504423 S2P_Cfg7_CSCTempsNum_39 "单个CSC中温度检测点的数目";
CM_ SG_ 2416504423 S2P_Cfg7_CSCCellTempsNum_39 "单个CSC中单芯温度检测点的数目(剔除电极温度)";
CM_ SG_ 2416504424 S2P_Cfg7_CSCCellSeries_Num_40 "单个CSC中电芯串联的数目";
CM_ SG_ 2416504424 S2P_Cfg7_CSCCellParal_Num_40 "单个CSC中电芯并联的数目";
CM_ SG_ 2416504424 S2P_Cfg7_CSCTempsNum_40 "单个CSC中温度检测点的数目";
CM_ SG_ 2416504424 S2P_Cfg7_CSCCellTempsNum_40 "单个CSC中单芯温度检测点的数目(剔除电极温度)";
CM_ SG_ 2416504425 S2P_Cfg7_CSCCellSeries_Num_41 "单个CSC中电芯串联的数目";
CM_ SG_ 2416504425 S2P_Cfg7_CSCCellParal_Num_41 "单个CSC中电芯并联的数目";
CM_ SG_ 2416504425 S2P_Cfg7_CSCTempsNum_41 "单个CSC中温度检测点的数目";
CM_ SG_ 2416504425 S2P_Cfg7_CSCCellTempsNum_41 "单个CSC中单芯温度检测点的数目(剔除电极温度)";
CM_ SG_ 2416504426 S2P_Cfg7_CSCCellSeries_Num_42 "单个CSC中电芯串联的数目";
CM_ SG_ 2416504426 S2P_Cfg7_CSCCellParal_Num_42 "单个CSC中电芯并联的数目";
CM_ SG_ 2416504426 S2P_Cfg7_CSCTempsNum_42 "单个CSC中温度检测点的数目";
CM_ SG_ 2416504426 S2P_Cfg7_CSCCellTempsNum_42 "单个CSC中单芯温度检测点的数目(剔除电极温度)";
CM_ SG_ 2416504427 S2P_Cfg7_CSCCellSeries_Num_43 "单个CSC中电芯串联的数目";
CM_ SG_ 2416504427 S2P_Cfg7_CSCCellParal_Num_43 "单个CSC中电芯并联的数目";
CM_ SG_ 2416504427 S2P_Cfg7_CSCTempsNum_43 "单个CSC中温度检测点的数目";
CM_ SG_ 2416504427 S2P_Cfg7_CSCCellTempsNum_43 "单个CSC中单芯温度检测点的数目(剔除电极温度)";
CM_ SG_ 2416504428 S2P_Cfg7_CSCCellSeries_Num_44 "单个CSC中电芯串联的数目";
CM_ SG_ 2416504428 S2P_Cfg7_CSCCellParal_Num_44 "单个CSC中电芯并联的数目";
CM_ SG_ 2416504428 S2P_Cfg7_CSCTempsNum_44 "单个CSC中温度检测点的数目";
CM_ SG_ 2416504428 S2P_Cfg7_CSCCellTempsNum_44 "单个CSC中单芯温度检测点的数目(剔除电极温度)";
CM_ SG_ 2416504429 S2P_Cfg7_CSCCellSeries_Num_45 "单个CSC中电芯串联的数目";
CM_ SG_ 2416504429 S2P_Cfg7_CSCCellParal_Num_45 "单个CSC中电芯并联的数目";
CM_ SG_ 2416504429 S2P_Cfg7_CSCTempsNum_45 "单个CSC中温度检测点的数目";
CM_ SG_ 2416504429 S2P_Cfg7_CSCCellTempsNum_45 "单个CSC中单芯温度检测点的数目(剔除电极温度)";
CM_ SG_ 2416504430 S2P_Cfg7_CSCCellSeries_Num_46 "单个CSC中电芯串联的数目";
CM_ SG_ 2416504430 S2P_Cfg7_CSCCellParal_Num_46 "单个CSC中电芯并联的数目";
CM_ SG_ 2416504430 S2P_Cfg7_CSCTempsNum_46 "单个CSC中温度检测点的数目";
CM_ SG_ 2416504430 S2P_Cfg7_CSCCellTempsNum_46 "单个CSC中单芯温度检测点的数目(剔除电极温度)";
CM_ SG_ 2416504431 S2P_Cfg7_CSCCellSeries_Num_47 "单个CSC中电芯串联的数目";
CM_ SG_ 2416504431 S2P_Cfg7_CSCCellParal_Num_47 "单个CSC中电芯并联的数目";
CM_ SG_ 2416504431 S2P_Cfg7_CSCTempsNum_47 "单个CSC中温度检测点的数目";
CM_ SG_ 2416504431 S2P_Cfg7_CSCCellTempsNum_47 "单个CSC中单芯温度检测点的数目(剔除电极温度)";
CM_ SG_ 2416504432 S2P_Cfg7_CSCCellSeries_Num_48 "单个CSC中电芯串联的数目";
CM_ SG_ 2416504432 S2P_Cfg7_CSCCellParal_Num_48 "单个CSC中电芯并联的数目";
CM_ SG_ 2416504432 S2P_Cfg7_CSCTempsNum_48 "单个CSC中温度检测点的数目";
CM_ SG_ 2416504432 S2P_Cfg7_CSCCellTempsNum_48 "单个CSC中单芯温度检测点的数目(剔除电极温度)";
CM_ SG_ 2416504433 S2P_Cfg7_CSCCellSeries_Num_49 "单个CSC中电芯串联的数目";
CM_ SG_ 2416504433 S2P_Cfg7_CSCCellParal_Num_49 "单个CSC中电芯并联的数目";
CM_ SG_ 2416504433 S2P_Cfg7_CSCTempsNum_49 "单个CSC中温度检测点的数目";
CM_ SG_ 2416504433 S2P_Cfg7_CSCCellTempsNum_49 "单个CSC中单芯温度检测点的数目(剔除电极温度)";
CM_ SG_ 2416504434 S2P_Cfg7_CSCCellSeries_Num_50 "单个CSC中电芯串联的数目";
CM_ SG_ 2416504434 S2P_Cfg7_CSCCellParal_Num_50 "单个CSC中电芯并联的数目";
CM_ SG_ 2416504434 S2P_Cfg7_CSCTempsNum_50 "单个CSC中温度检测点的数目";
CM_ SG_ 2416504434 S2P_Cfg7_CSCCellTempsNum_50 "单个CSC中单芯温度检测点的数目(剔除电极温度)";
CM_ SG_ 2416504435 S2P_Cfg7_CSCCellSeries_Num_51 "单个CSC中电芯串联的数目";
CM_ SG_ 2416504435 S2P_Cfg7_CSCCellParal_Num_51 "单个CSC中电芯并联的数目";
CM_ SG_ 2416504435 S2P_Cfg7_CSCTempsNum_51 "单个CSC中温度检测点的数目";
CM_ SG_ 2416504435 S2P_Cfg7_CSCCellTempsNum_51 "单个CSC中单芯温度检测点的数目(剔除电极温度)";
CM_ SG_ 2416504436 S2P_Cfg7_CSCCellSeries_Num_52 "单个CSC中电芯串联的数目";
CM_ SG_ 2416504436 S2P_Cfg7_CSCCellParal_Num_52 "单个CSC中电芯并联的数目";
CM_ SG_ 2416504436 S2P_Cfg7_CSCTempsNum_52 "单个CSC中温度检测点的数目";
CM_ SG_ 2416504436 S2P_Cfg7_CSCCellTempsNum_52 "单个CSC中单芯温度检测点的数目(剔除电极温度)";
CM_ SG_ 2416504437 S2P_Cfg7_CSCCellSeries_Num_53 "单个CSC中电芯串联的数目";
CM_ SG_ 2416504437 S2P_Cfg7_CSCCellParal_Num_53 "单个CSC中电芯并联的数目";
CM_ SG_ 2416504437 S2P_Cfg7_CSCTempsNum_53 "单个CSC中温度检测点的数目";
CM_ SG_ 2416504437 S2P_Cfg7_CSCCellTempsNum_53 "单个CSC中单芯温度检测点的数目(剔除电极温度)";
CM_ SG_ 2416504438 S2P_Cfg7_CSCCellSeries_Num_54 "单个CSC中电芯串联的数目";
CM_ SG_ 2416504438 S2P_Cfg7_CSCCellParal_Num_54 "单个CSC中电芯并联的数目";
CM_ SG_ 2416504438 S2P_Cfg7_CSCTempsNum_54 "单个CSC中温度检测点的数目";
CM_ SG_ 2416504438 S2P_Cfg7_CSCCellTempsNum_54 "单个CSC中单芯温度检测点的数目(剔除电极温度)";
CM_ SG_ 2416504439 S2P_Cfg7_CSCCellSeries_Num_55 "单个CSC中电芯串联的数目";
CM_ SG_ 2416504439 S2P_Cfg7_CSCCellParal_Num_55 "单个CSC中电芯并联的数目";
CM_ SG_ 2416504439 S2P_Cfg7_CSCTempsNum_55 "单个CSC中温度检测点的数目";
CM_ SG_ 2416504439 S2P_Cfg7_CSCCellTempsNum_55 "单个CSC中单芯温度检测点的数目(剔除电极温度)";
CM_ SG_ 2416504440 S2P_Cfg7_CSCCellSeries_Num_56 "单个CSC中电芯串联的数目";
CM_ SG_ 2416504440 S2P_Cfg7_CSCCellParal_Num_56 "单个CSC中电芯并联的数目";
CM_ SG_ 2416504440 S2P_Cfg7_CSCTempsNum_56 "单个CSC中温度检测点的数目";
CM_ SG_ 2416504440 S2P_Cfg7_CSCCellTempsNum_56 "单个CSC中单芯温度检测点的数目(剔除电极温度)";
CM_ SG_ 2416504441 S2P_Cfg7_CSCCellSeries_Num_57 "单个CSC中电芯串联的数目";
CM_ SG_ 2416504441 S2P_Cfg7_CSCCellParal_Num_57 "单个CSC中电芯并联的数目";
CM_ SG_ 2416504441 S2P_Cfg7_CSCTempsNum_57 "单个CSC中温度检测点的数目";
CM_ SG_ 2416504441 S2P_Cfg7_CSCCellTempsNum_57 "单个CSC中单芯温度检测点的数目(剔除电极温度)";
CM_ SG_ 2416504442 S2P_Cfg7_CSCCellSeries_Num_58 "单个CSC中电芯串联的数目";
CM_ SG_ 2416504442 S2P_Cfg7_CSCCellParal_Num_58 "单个CSC中电芯并联的数目";
CM_ SG_ 2416504442 S2P_Cfg7_CSCTempsNum_58 "单个CSC中温度检测点的数目";
CM_ SG_ 2416504442 S2P_Cfg7_CSCCellTempsNum_58 "单个CSC中单芯温度检测点的数目(剔除电极温度)";
CM_ SG_ 2416504443 S2P_Cfg7_CSCCellSeries_Num_59 "单个CSC中电芯串联的数目";
CM_ SG_ 2416504443 S2P_Cfg7_CSCCellParal_Num_59 "单个CSC中电芯并联的数目";
CM_ SG_ 2416504443 S2P_Cfg7_CSCTempsNum_59 "单个CSC中温度检测点的数目";
CM_ SG_ 2416504443 S2P_Cfg7_CSCCellTempsNum_59 "单个CSC中单芯温度检测点的数目(剔除电极温度)";
CM_ SG_ 2416504444 S2P_Cfg7_CSCCellSeries_Num_60 "单个CSC中电芯串联的数目";
CM_ SG_ 2416504444 S2P_Cfg7_CSCCellParal_Num_60 "单个CSC中电芯并联的数目";
CM_ SG_ 2416504444 S2P_Cfg7_CSCTempsNum_60 "单个CSC中温度检测点的数目";
CM_ SG_ 2416504444 S2P_Cfg7_CSCCellTempsNum_60 "单个CSC中单芯温度检测点的数目(剔除电极温度)";
CM_ SG_ 2416504445 S2P_Cfg7_CSCCellSeries_Num_61 "单个CSC中电芯串联的数目";
CM_ SG_ 2416504445 S2P_Cfg7_CSCCellParal_Num_61 "单个CSC中电芯并联的数目";
CM_ SG_ 2416504445 S2P_Cfg7_CSCTempsNum_61 "单个CSC中温度检测点的数目";
CM_ SG_ 2416504445 S2P_Cfg7_CSCCellTempsNum_61 "单个CSC中单芯温度检测点的数目(剔除电极温度)";
CM_ SG_ 2416504446 S2P_Cfg7_CSCCellSeries_Num_62 "单个CSC中电芯串联的数目";
CM_ SG_ 2416504446 S2P_Cfg7_CSCCellParal_Num_62 "单个CSC中电芯并联的数目";
CM_ SG_ 2416504446 S2P_Cfg7_CSCTempsNum_62 "单个CSC中温度检测点的数目";
CM_ SG_ 2416504446 S2P_Cfg7_CSCCellTempsNum_62 "单个CSC中单芯温度检测点的数目(剔除电极温度)";
CM_ SG_ 2416504447 S2P_Cfg7_CSCCellSeries_Num_63 "单个CSC中电芯串联的数目";
CM_ SG_ 2416504447 S2P_Cfg7_CSCCellParal_Num_63 "单个CSC中电芯并联的数目";
CM_ SG_ 2416504447 S2P_Cfg7_CSCTempsNum_63 "单个CSC中温度检测点的数目";
CM_ SG_ 2416504447 S2P_Cfg7_CSCCellTempsNum_63 "单个CSC中单芯温度检测点的数目(剔除电极温度)";
CM_ SG_ 2417552961 S2P_Cfg8_SW_Ver_Byte1_01 "CSC软件版本号最低字节Byte1对应的ASCII码";
CM_ SG_ 2417552961 S2P_Cfg8_SW_Ver_Byte2_01 "CSC软件版本号Byte2对应的ASCII码";
CM_ SG_ 2417552961 S2P_Cfg8_SW_Ver_Byte3_01 "CSC软件版本号Byte3对应的ASCII码";
CM_ SG_ 2417552961 S2P_Cfg8_SW_Ver_Byte4_01 "CSC软件版本号Byte4对应的ASCII码";
CM_ SG_ 2417552961 S2P_Cfg8_SW_Ver_Byte5_01 "CSC软件版本号Byte5对应的ASCII码";
CM_ SG_ 2417552961 S2P_Cfg8_SW_Ver_Byte6_01 "CSC软件版本号Byte6对应的ASCII码";
CM_ SG_ 2417552961 S2P_Cfg8_SW_Ver_Byte7_01 "CSC软件版本号Byte7对应的ASCII码";
CM_ SG_ 2417552961 S2P_Cfg8_SW_Ver_Byte8_01 "CSC软件版本号Byte8对应的ASCII码";
CM_ SG_ 2417552962 S2P_Cfg8_SW_Ver_Byte1_02 "CSC软件版本号最低字节Byte1对应的ASCII码";
CM_ SG_ 2417552962 S2P_Cfg8_SW_Ver_Byte2_02 "CSC软件版本号Byte2对应的ASCII码";
CM_ SG_ 2417552962 S2P_Cfg8_SW_Ver_Byte3_02 "CSC软件版本号Byte3对应的ASCII码";
CM_ SG_ 2417552962 S2P_Cfg8_SW_Ver_Byte4_02 "CSC软件版本号Byte4对应的ASCII码";
CM_ SG_ 2417552962 S2P_Cfg8_SW_Ver_Byte5_02 "CSC软件版本号Byte5对应的ASCII码";
CM_ SG_ 2417552962 S2P_Cfg8_SW_Ver_Byte6_02 "CSC软件版本号Byte6对应的ASCII码";
CM_ SG_ 2417552962 S2P_Cfg8_SW_Ver_Byte7_02 "CSC软件版本号Byte7对应的ASCII码";
CM_ SG_ 2417552962 S2P_Cfg8_SW_Ver_Byte8_02 "CSC软件版本号Byte8对应的ASCII码";
CM_ SG_ 2417552963 S2P_Cfg8_SW_Ver_Byte1_03 "CSC软件版本号最低字节Byte1对应的ASCII码";
CM_ SG_ 2417552963 S2P_Cfg8_SW_Ver_Byte2_03 "CSC软件版本号Byte2对应的ASCII码";
CM_ SG_ 2417552963 S2P_Cfg8_SW_Ver_Byte3_03 "CSC软件版本号Byte3对应的ASCII码";
CM_ SG_ 2417552963 S2P_Cfg8_SW_Ver_Byte4_03 "CSC软件版本号Byte4对应的ASCII码";
CM_ SG_ 2417552963 S2P_Cfg8_SW_Ver_Byte5_03 "CSC软件版本号Byte5对应的ASCII码";
CM_ SG_ 2417552963 S2P_Cfg8_SW_Ver_Byte6_03 "CSC软件版本号Byte6对应的ASCII码";
CM_ SG_ 2417552963 S2P_Cfg8_SW_Ver_Byte7_03 "CSC软件版本号Byte7对应的ASCII码";
CM_ SG_ 2417552963 S2P_Cfg8_SW_Ver_Byte8_03 "CSC软件版本号Byte8对应的ASCII码";
CM_ SG_ 2417552964 S2P_Cfg8_SW_Ver_Byte1_04 "CSC软件版本号最低字节Byte1对应的ASCII码";
CM_ SG_ 2417552964 S2P_Cfg8_SW_Ver_Byte2_04 "CSC软件版本号Byte2对应的ASCII码";
CM_ SG_ 2417552964 S2P_Cfg8_SW_Ver_Byte3_04 "CSC软件版本号Byte3对应的ASCII码";
CM_ SG_ 2417552964 S2P_Cfg8_SW_Ver_Byte4_04 "CSC软件版本号Byte4对应的ASCII码";
CM_ SG_ 2417552964 S2P_Cfg8_SW_Ver_Byte5_04 "CSC软件版本号Byte5对应的ASCII码";
CM_ SG_ 2417552964 S2P_Cfg8_SW_Ver_Byte6_04 "CSC软件版本号Byte6对应的ASCII码";
CM_ SG_ 2417552964 S2P_Cfg8_SW_Ver_Byte7_04 "CSC软件版本号Byte7对应的ASCII码";
CM_ SG_ 2417552964 S2P_Cfg8_SW_Ver_Byte8_04 "CSC软件版本号Byte8对应的ASCII码";
CM_ SG_ 2417552965 S2P_Cfg8_SW_Ver_Byte1_05 "CSC软件版本号最低字节Byte1对应的ASCII码";
CM_ SG_ 2417552965 S2P_Cfg8_SW_Ver_Byte2_05 "CSC软件版本号Byte2对应的ASCII码";
CM_ SG_ 2417552965 S2P_Cfg8_SW_Ver_Byte3_05 "CSC软件版本号Byte3对应的ASCII码";
CM_ SG_ 2417552965 S2P_Cfg8_SW_Ver_Byte4_05 "CSC软件版本号Byte4对应的ASCII码";
CM_ SG_ 2417552965 S2P_Cfg8_SW_Ver_Byte5_05 "CSC软件版本号Byte5对应的ASCII码";
CM_ SG_ 2417552965 S2P_Cfg8_SW_Ver_Byte6_05 "CSC软件版本号Byte6对应的ASCII码";
CM_ SG_ 2417552965 S2P_Cfg8_SW_Ver_Byte7_05 "CSC软件版本号Byte7对应的ASCII码";
CM_ SG_ 2417552965 S2P_Cfg8_SW_Ver_Byte8_05 "CSC软件版本号Byte8对应的ASCII码";
CM_ SG_ 2417552966 S2P_Cfg8_SW_Ver_Byte1_06 "CSC软件版本号最低字节Byte1对应的ASCII码";
CM_ SG_ 2417552966 S2P_Cfg8_SW_Ver_Byte2_06 "CSC软件版本号Byte2对应的ASCII码";
CM_ SG_ 2417552966 S2P_Cfg8_SW_Ver_Byte3_06 "CSC软件版本号Byte3对应的ASCII码";
CM_ SG_ 2417552966 S2P_Cfg8_SW_Ver_Byte4_06 "CSC软件版本号Byte4对应的ASCII码";
CM_ SG_ 2417552966 S2P_Cfg8_SW_Ver_Byte5_06 "CSC软件版本号Byte5对应的ASCII码";
CM_ SG_ 2417552966 S2P_Cfg8_SW_Ver_Byte6_06 "CSC软件版本号Byte6对应的ASCII码";
CM_ SG_ 2417552966 S2P_Cfg8_SW_Ver_Byte7_06 "CSC软件版本号Byte7对应的ASCII码";
CM_ SG_ 2417552966 S2P_Cfg8_SW_Ver_Byte8_06 "CSC软件版本号Byte8对应的ASCII码";
CM_ SG_ 2417552967 S2P_Cfg8_SW_Ver_Byte1_07 "CSC软件版本号最低字节Byte1对应的ASCII码";
CM_ SG_ 2417552967 S2P_Cfg8_SW_Ver_Byte2_07 "CSC软件版本号Byte2对应的ASCII码";
CM_ SG_ 2417552967 S2P_Cfg8_SW_Ver_Byte3_07 "CSC软件版本号Byte3对应的ASCII码";
CM_ SG_ 2417552967 S2P_Cfg8_SW_Ver_Byte4_07 "CSC软件版本号Byte4对应的ASCII码";
CM_ SG_ 2417552967 S2P_Cfg8_SW_Ver_Byte5_07 "CSC软件版本号Byte5对应的ASCII码";
CM_ SG_ 2417552967 S2P_Cfg8_SW_Ver_Byte6_07 "CSC软件版本号Byte6对应的ASCII码";
CM_ SG_ 2417552967 S2P_Cfg8_SW_Ver_Byte7_07 "CSC软件版本号Byte7对应的ASCII码";
CM_ SG_ 2417552967 S2P_Cfg8_SW_Ver_Byte8_07 "CSC软件版本号Byte8对应的ASCII码";
CM_ SG_ 2417552968 S2P_Cfg8_SW_Ver_Byte1_08 "CSC软件版本号最低字节Byte1对应的ASCII码";
CM_ SG_ 2417552968 S2P_Cfg8_SW_Ver_Byte2_08 "CSC软件版本号Byte2对应的ASCII码";
CM_ SG_ 2417552968 S2P_Cfg8_SW_Ver_Byte3_08 "CSC软件版本号Byte3对应的ASCII码";
CM_ SG_ 2417552968 S2P_Cfg8_SW_Ver_Byte4_08 "CSC软件版本号Byte4对应的ASCII码";
CM_ SG_ 2417552968 S2P_Cfg8_SW_Ver_Byte5_08 "CSC软件版本号Byte5对应的ASCII码";
CM_ SG_ 2417552968 S2P_Cfg8_SW_Ver_Byte6_08 "CSC软件版本号Byte6对应的ASCII码";
CM_ SG_ 2417552968 S2P_Cfg8_SW_Ver_Byte7_08 "CSC软件版本号Byte7对应的ASCII码";
CM_ SG_ 2417552968 S2P_Cfg8_SW_Ver_Byte8_08 "CSC软件版本号Byte8对应的ASCII码";
CM_ SG_ 2417552969 S2P_Cfg8_SW_Ver_Byte1_09 "CSC软件版本号最低字节Byte1对应的ASCII码";
CM_ SG_ 2417552969 S2P_Cfg8_SW_Ver_Byte2_09 "CSC软件版本号Byte2对应的ASCII码";
CM_ SG_ 2417552969 S2P_Cfg8_SW_Ver_Byte3_09 "CSC软件版本号Byte3对应的ASCII码";
CM_ SG_ 2417552969 S2P_Cfg8_SW_Ver_Byte4_09 "CSC软件版本号Byte4对应的ASCII码";
CM_ SG_ 2417552969 S2P_Cfg8_SW_Ver_Byte5_09 "CSC软件版本号Byte5对应的ASCII码";
CM_ SG_ 2417552969 S2P_Cfg8_SW_Ver_Byte6_09 "CSC软件版本号Byte6对应的ASCII码";
CM_ SG_ 2417552969 S2P_Cfg8_SW_Ver_Byte7_09 "CSC软件版本号Byte7对应的ASCII码";
CM_ SG_ 2417552969 S2P_Cfg8_SW_Ver_Byte8_09 "CSC软件版本号Byte8对应的ASCII码";
CM_ SG_ 2417552970 S2P_Cfg8_SW_Ver_Byte1_10 "CSC软件版本号最低字节Byte1对应的ASCII码";
CM_ SG_ 2417552970 S2P_Cfg8_SW_Ver_Byte2_10 "CSC软件版本号Byte2对应的ASCII码";
CM_ SG_ 2417552970 S2P_Cfg8_SW_Ver_Byte3_10 "CSC软件版本号Byte3对应的ASCII码";
CM_ SG_ 2417552970 S2P_Cfg8_SW_Ver_Byte4_10 "CSC软件版本号Byte4对应的ASCII码";
CM_ SG_ 2417552970 S2P_Cfg8_SW_Ver_Byte5_10 "CSC软件版本号Byte5对应的ASCII码";
CM_ SG_ 2417552970 S2P_Cfg8_SW_Ver_Byte6_10 "CSC软件版本号Byte6对应的ASCII码";
CM_ SG_ 2417552970 S2P_Cfg8_SW_Ver_Byte7_10 "CSC软件版本号Byte7对应的ASCII码";
CM_ SG_ 2417552970 S2P_Cfg8_SW_Ver_Byte8_10 "CSC软件版本号Byte8对应的ASCII码";
CM_ SG_ 2417552971 S2P_Cfg8_SW_Ver_Byte1_11 "CSC软件版本号最低字节Byte1对应的ASCII码";
CM_ SG_ 2417552971 S2P_Cfg8_SW_Ver_Byte2_11 "CSC软件版本号Byte2对应的ASCII码";
CM_ SG_ 2417552971 S2P_Cfg8_SW_Ver_Byte3_11 "CSC软件版本号Byte3对应的ASCII码";
CM_ SG_ 2417552971 S2P_Cfg8_SW_Ver_Byte4_11 "CSC软件版本号Byte4对应的ASCII码";
CM_ SG_ 2417552971 S2P_Cfg8_SW_Ver_Byte5_11 "CSC软件版本号Byte5对应的ASCII码";
CM_ SG_ 2417552971 S2P_Cfg8_SW_Ver_Byte6_11 "CSC软件版本号Byte6对应的ASCII码";
CM_ SG_ 2417552971 S2P_Cfg8_SW_Ver_Byte7_11 "CSC软件版本号Byte7对应的ASCII码";
CM_ SG_ 2417552971 S2P_Cfg8_SW_Ver_Byte8_11 "CSC软件版本号Byte8对应的ASCII码";
CM_ SG_ 2417552972 S2P_Cfg8_SW_Ver_Byte1_12 "CSC软件版本号最低字节Byte1对应的ASCII码";
CM_ SG_ 2417552972 S2P_Cfg8_SW_Ver_Byte2_12 "CSC软件版本号Byte2对应的ASCII码";
CM_ SG_ 2417552972 S2P_Cfg8_SW_Ver_Byte3_12 "CSC软件版本号Byte3对应的ASCII码";
CM_ SG_ 2417552972 S2P_Cfg8_SW_Ver_Byte4_12 "CSC软件版本号Byte4对应的ASCII码";
CM_ SG_ 2417552972 S2P_Cfg8_SW_Ver_Byte5_12 "CSC软件版本号Byte5对应的ASCII码";
CM_ SG_ 2417552972 S2P_Cfg8_SW_Ver_Byte6_12 "CSC软件版本号Byte6对应的ASCII码";
CM_ SG_ 2417552972 S2P_Cfg8_SW_Ver_Byte7_12 "CSC软件版本号Byte7对应的ASCII码";
CM_ SG_ 2417552972 S2P_Cfg8_SW_Ver_Byte8_12 "CSC软件版本号Byte8对应的ASCII码";
CM_ SG_ 2417552973 S2P_Cfg8_SW_Ver_Byte1_13 "CSC软件版本号最低字节Byte1对应的ASCII码";
CM_ SG_ 2417552973 S2P_Cfg8_SW_Ver_Byte2_13 "CSC软件版本号Byte2对应的ASCII码";
CM_ SG_ 2417552973 S2P_Cfg8_SW_Ver_Byte3_13 "CSC软件版本号Byte3对应的ASCII码";
CM_ SG_ 2417552973 S2P_Cfg8_SW_Ver_Byte4_13 "CSC软件版本号Byte4对应的ASCII码";
CM_ SG_ 2417552973 S2P_Cfg8_SW_Ver_Byte5_13 "CSC软件版本号Byte5对应的ASCII码";
CM_ SG_ 2417552973 S2P_Cfg8_SW_Ver_Byte6_13 "CSC软件版本号Byte6对应的ASCII码";
CM_ SG_ 2417552973 S2P_Cfg8_SW_Ver_Byte7_13 "CSC软件版本号Byte7对应的ASCII码";
CM_ SG_ 2417552973 S2P_Cfg8_SW_Ver_Byte8_13 "CSC软件版本号Byte8对应的ASCII码";
CM_ SG_ 2417552974 S2P_Cfg8_SW_Ver_Byte1_14 "CSC软件版本号最低字节Byte1对应的ASCII码";
CM_ SG_ 2417552974 S2P_Cfg8_SW_Ver_Byte2_14 "CSC软件版本号Byte2对应的ASCII码";
CM_ SG_ 2417552974 S2P_Cfg8_SW_Ver_Byte3_14 "CSC软件版本号Byte3对应的ASCII码";
CM_ SG_ 2417552974 S2P_Cfg8_SW_Ver_Byte4_14 "CSC软件版本号Byte4对应的ASCII码";
CM_ SG_ 2417552974 S2P_Cfg8_SW_Ver_Byte5_14 "CSC软件版本号Byte5对应的ASCII码";
CM_ SG_ 2417552974 S2P_Cfg8_SW_Ver_Byte6_14 "CSC软件版本号Byte6对应的ASCII码";
CM_ SG_ 2417552974 S2P_Cfg8_SW_Ver_Byte7_14 "CSC软件版本号Byte7对应的ASCII码";
CM_ SG_ 2417552974 S2P_Cfg8_SW_Ver_Byte8_14 "CSC软件版本号Byte8对应的ASCII码";
CM_ SG_ 2417552975 S2P_Cfg8_SW_Ver_Byte1_15 "CSC软件版本号最低字节Byte1对应的ASCII码";
CM_ SG_ 2417552975 S2P_Cfg8_SW_Ver_Byte2_15 "CSC软件版本号Byte2对应的ASCII码";
CM_ SG_ 2417552975 S2P_Cfg8_SW_Ver_Byte3_15 "CSC软件版本号Byte3对应的ASCII码";
CM_ SG_ 2417552975 S2P_Cfg8_SW_Ver_Byte4_15 "CSC软件版本号Byte4对应的ASCII码";
CM_ SG_ 2417552975 S2P_Cfg8_SW_Ver_Byte5_15 "CSC软件版本号Byte5对应的ASCII码";
CM_ SG_ 2417552975 S2P_Cfg8_SW_Ver_Byte6_15 "CSC软件版本号Byte6对应的ASCII码";
CM_ SG_ 2417552975 S2P_Cfg8_SW_Ver_Byte7_15 "CSC软件版本号Byte7对应的ASCII码";
CM_ SG_ 2417552975 S2P_Cfg8_SW_Ver_Byte8_15 "CSC软件版本号Byte8对应的ASCII码";
CM_ SG_ 2417552976 S2P_Cfg8_SW_Ver_Byte1_16 "CSC软件版本号最低字节Byte1对应的ASCII码";
CM_ SG_ 2417552976 S2P_Cfg8_SW_Ver_Byte2_16 "CSC软件版本号Byte2对应的ASCII码";
CM_ SG_ 2417552976 S2P_Cfg8_SW_Ver_Byte3_16 "CSC软件版本号Byte3对应的ASCII码";
CM_ SG_ 2417552976 S2P_Cfg8_SW_Ver_Byte4_16 "CSC软件版本号Byte4对应的ASCII码";
CM_ SG_ 2417552976 S2P_Cfg8_SW_Ver_Byte5_16 "CSC软件版本号Byte5对应的ASCII码";
CM_ SG_ 2417552976 S2P_Cfg8_SW_Ver_Byte6_16 "CSC软件版本号Byte6对应的ASCII码";
CM_ SG_ 2417552976 S2P_Cfg8_SW_Ver_Byte7_16 "CSC软件版本号Byte7对应的ASCII码";
CM_ SG_ 2417552976 S2P_Cfg8_SW_Ver_Byte8_16 "CSC软件版本号Byte8对应的ASCII码";
CM_ SG_ 2417552977 S2P_Cfg8_SW_Ver_Byte1_17 "CSC软件版本号最低字节Byte1对应的ASCII码";
CM_ SG_ 2417552977 S2P_Cfg8_SW_Ver_Byte2_17 "CSC软件版本号Byte2对应的ASCII码";
CM_ SG_ 2417552977 S2P_Cfg8_SW_Ver_Byte3_17 "CSC软件版本号Byte3对应的ASCII码";
CM_ SG_ 2417552977 S2P_Cfg8_SW_Ver_Byte4_17 "CSC软件版本号Byte4对应的ASCII码";
CM_ SG_ 2417552977 S2P_Cfg8_SW_Ver_Byte5_17 "CSC软件版本号Byte5对应的ASCII码";
CM_ SG_ 2417552977 S2P_Cfg8_SW_Ver_Byte6_17 "CSC软件版本号Byte6对应的ASCII码";
CM_ SG_ 2417552977 S2P_Cfg8_SW_Ver_Byte7_17 "CSC软件版本号Byte7对应的ASCII码";
CM_ SG_ 2417552977 S2P_Cfg8_SW_Ver_Byte8_17 "CSC软件版本号Byte8对应的ASCII码";
CM_ SG_ 2417552978 S2P_Cfg8_SW_Ver_Byte1_18 "CSC软件版本号最低字节Byte1对应的ASCII码";
CM_ SG_ 2417552978 S2P_Cfg8_SW_Ver_Byte2_18 "CSC软件版本号Byte2对应的ASCII码";
CM_ SG_ 2417552978 S2P_Cfg8_SW_Ver_Byte3_18 "CSC软件版本号Byte3对应的ASCII码";
CM_ SG_ 2417552978 S2P_Cfg8_SW_Ver_Byte4_18 "CSC软件版本号Byte4对应的ASCII码";
CM_ SG_ 2417552978 S2P_Cfg8_SW_Ver_Byte5_18 "CSC软件版本号Byte5对应的ASCII码";
CM_ SG_ 2417552978 S2P_Cfg8_SW_Ver_Byte6_18 "CSC软件版本号Byte6对应的ASCII码";
CM_ SG_ 2417552978 S2P_Cfg8_SW_Ver_Byte7_18 "CSC软件版本号Byte7对应的ASCII码";
CM_ SG_ 2417552978 S2P_Cfg8_SW_Ver_Byte8_18 "CSC软件版本号Byte8对应的ASCII码";
CM_ SG_ 2417552979 S2P_Cfg8_SW_Ver_Byte1_19 "CSC软件版本号最低字节Byte1对应的ASCII码";
CM_ SG_ 2417552979 S2P_Cfg8_SW_Ver_Byte2_19 "CSC软件版本号Byte2对应的ASCII码";
CM_ SG_ 2417552979 S2P_Cfg8_SW_Ver_Byte3_19 "CSC软件版本号Byte3对应的ASCII码";
CM_ SG_ 2417552979 S2P_Cfg8_SW_Ver_Byte4_19 "CSC软件版本号Byte4对应的ASCII码";
CM_ SG_ 2417552979 S2P_Cfg8_SW_Ver_Byte5_19 "CSC软件版本号Byte5对应的ASCII码";
CM_ SG_ 2417552979 S2P_Cfg8_SW_Ver_Byte6_19 "CSC软件版本号Byte6对应的ASCII码";
CM_ SG_ 2417552979 S2P_Cfg8_SW_Ver_Byte7_19 "CSC软件版本号Byte7对应的ASCII码";
CM_ SG_ 2417552979 S2P_Cfg8_SW_Ver_Byte8_19 "CSC软件版本号Byte8对应的ASCII码";
CM_ SG_ 2417552980 S2P_Cfg8_SW_Ver_Byte1_20 "CSC软件版本号最低字节Byte1对应的ASCII码";
CM_ SG_ 2417552980 S2P_Cfg8_SW_Ver_Byte2_20 "CSC软件版本号Byte2对应的ASCII码";
CM_ SG_ 2417552980 S2P_Cfg8_SW_Ver_Byte3_20 "CSC软件版本号Byte3对应的ASCII码";
CM_ SG_ 2417552980 S2P_Cfg8_SW_Ver_Byte4_20 "CSC软件版本号Byte4对应的ASCII码";
CM_ SG_ 2417552980 S2P_Cfg8_SW_Ver_Byte5_20 "CSC软件版本号Byte5对应的ASCII码";
CM_ SG_ 2417552980 S2P_Cfg8_SW_Ver_Byte6_20 "CSC软件版本号Byte6对应的ASCII码";
CM_ SG_ 2417552980 S2P_Cfg8_SW_Ver_Byte7_20 "CSC软件版本号Byte7对应的ASCII码";
CM_ SG_ 2417552980 S2P_Cfg8_SW_Ver_Byte8_20 "CSC软件版本号Byte8对应的ASCII码";
CM_ SG_ 2417552981 S2P_Cfg8_SW_Ver_Byte1_21 "CSC软件版本号最低字节Byte1对应的ASCII码";
CM_ SG_ 2417552981 S2P_Cfg8_SW_Ver_Byte2_21 "CSC软件版本号Byte2对应的ASCII码";
CM_ SG_ 2417552981 S2P_Cfg8_SW_Ver_Byte3_21 "CSC软件版本号Byte3对应的ASCII码";
CM_ SG_ 2417552981 S2P_Cfg8_SW_Ver_Byte4_21 "CSC软件版本号Byte4对应的ASCII码";
CM_ SG_ 2417552981 S2P_Cfg8_SW_Ver_Byte5_21 "CSC软件版本号Byte5对应的ASCII码";
CM_ SG_ 2417552981 S2P_Cfg8_SW_Ver_Byte6_21 "CSC软件版本号Byte6对应的ASCII码";
CM_ SG_ 2417552981 S2P_Cfg8_SW_Ver_Byte7_21 "CSC软件版本号Byte7对应的ASCII码";
CM_ SG_ 2417552981 S2P_Cfg8_SW_Ver_Byte8_21 "CSC软件版本号Byte8对应的ASCII码";
CM_ SG_ 2417552982 S2P_Cfg8_SW_Ver_Byte1_22 "CSC软件版本号最低字节Byte1对应的ASCII码";
CM_ SG_ 2417552982 S2P_Cfg8_SW_Ver_Byte2_22 "CSC软件版本号Byte2对应的ASCII码";
CM_ SG_ 2417552982 S2P_Cfg8_SW_Ver_Byte3_22 "CSC软件版本号Byte3对应的ASCII码";
CM_ SG_ 2417552982 S2P_Cfg8_SW_Ver_Byte4_22 "CSC软件版本号Byte4对应的ASCII码";
CM_ SG_ 2417552982 S2P_Cfg8_SW_Ver_Byte5_22 "CSC软件版本号Byte5对应的ASCII码";
CM_ SG_ 2417552982 S2P_Cfg8_SW_Ver_Byte6_22 "CSC软件版本号Byte6对应的ASCII码";
CM_ SG_ 2417552982 S2P_Cfg8_SW_Ver_Byte7_22 "CSC软件版本号Byte7对应的ASCII码";
CM_ SG_ 2417552982 S2P_Cfg8_SW_Ver_Byte8_22 "CSC软件版本号Byte8对应的ASCII码";
CM_ SG_ 2417552983 S2P_Cfg8_SW_Ver_Byte1_23 "CSC软件版本号最低字节Byte1对应的ASCII码";
CM_ SG_ 2417552983 S2P_Cfg8_SW_Ver_Byte2_23 "CSC软件版本号Byte2对应的ASCII码";
CM_ SG_ 2417552983 S2P_Cfg8_SW_Ver_Byte3_23 "CSC软件版本号Byte3对应的ASCII码";
CM_ SG_ 2417552983 S2P_Cfg8_SW_Ver_Byte4_23 "CSC软件版本号Byte4对应的ASCII码";
CM_ SG_ 2417552983 S2P_Cfg8_SW_Ver_Byte5_23 "CSC软件版本号Byte5对应的ASCII码";
CM_ SG_ 2417552983 S2P_Cfg8_SW_Ver_Byte6_23 "CSC软件版本号Byte6对应的ASCII码";
CM_ SG_ 2417552983 S2P_Cfg8_SW_Ver_Byte7_23 "CSC软件版本号Byte7对应的ASCII码";
CM_ SG_ 2417552983 S2P_Cfg8_SW_Ver_Byte8_23 "CSC软件版本号Byte8对应的ASCII码";
CM_ SG_ 2417552984 S2P_Cfg8_SW_Ver_Byte1_24 "CSC软件版本号最低字节Byte1对应的ASCII码";
CM_ SG_ 2417552984 S2P_Cfg8_SW_Ver_Byte2_24 "CSC软件版本号Byte2对应的ASCII码";
CM_ SG_ 2417552984 S2P_Cfg8_SW_Ver_Byte3_24 "CSC软件版本号Byte3对应的ASCII码";
CM_ SG_ 2417552984 S2P_Cfg8_SW_Ver_Byte4_24 "CSC软件版本号Byte4对应的ASCII码";
CM_ SG_ 2417552984 S2P_Cfg8_SW_Ver_Byte5_24 "CSC软件版本号Byte5对应的ASCII码";
CM_ SG_ 2417552984 S2P_Cfg8_SW_Ver_Byte6_24 "CSC软件版本号Byte6对应的ASCII码";
CM_ SG_ 2417552984 S2P_Cfg8_SW_Ver_Byte7_24 "CSC软件版本号Byte7对应的ASCII码";
CM_ SG_ 2417552984 S2P_Cfg8_SW_Ver_Byte8_24 "CSC软件版本号Byte8对应的ASCII码";
CM_ SG_ 2417552985 S2P_Cfg8_SW_Ver_Byte1_25 "CSC软件版本号最低字节Byte1对应的ASCII码";
CM_ SG_ 2417552985 S2P_Cfg8_SW_Ver_Byte2_25 "CSC软件版本号Byte2对应的ASCII码";
CM_ SG_ 2417552985 S2P_Cfg8_SW_Ver_Byte3_25 "CSC软件版本号Byte3对应的ASCII码";
CM_ SG_ 2417552985 S2P_Cfg8_SW_Ver_Byte4_25 "CSC软件版本号Byte4对应的ASCII码";
CM_ SG_ 2417552985 S2P_Cfg8_SW_Ver_Byte5_25 "CSC软件版本号Byte5对应的ASCII码";
CM_ SG_ 2417552985 S2P_Cfg8_SW_Ver_Byte6_25 "CSC软件版本号Byte6对应的ASCII码";
CM_ SG_ 2417552985 S2P_Cfg8_SW_Ver_Byte7_25 "CSC软件版本号Byte7对应的ASCII码";
CM_ SG_ 2417552985 S2P_Cfg8_SW_Ver_Byte8_25 "CSC软件版本号Byte8对应的ASCII码";
CM_ SG_ 2417552986 S2P_Cfg8_SW_Ver_Byte1_26 "CSC软件版本号最低字节Byte1对应的ASCII码";
CM_ SG_ 2417552986 S2P_Cfg8_SW_Ver_Byte2_26 "CSC软件版本号Byte2对应的ASCII码";
CM_ SG_ 2417552986 S2P_Cfg8_SW_Ver_Byte3_26 "CSC软件版本号Byte3对应的ASCII码";
CM_ SG_ 2417552986 S2P_Cfg8_SW_Ver_Byte4_26 "CSC软件版本号Byte4对应的ASCII码";
CM_ SG_ 2417552986 S2P_Cfg8_SW_Ver_Byte5_26 "CSC软件版本号Byte5对应的ASCII码";
CM_ SG_ 2417552986 S2P_Cfg8_SW_Ver_Byte6_26 "CSC软件版本号Byte6对应的ASCII码";
CM_ SG_ 2417552986 S2P_Cfg8_SW_Ver_Byte7_26 "CSC软件版本号Byte7对应的ASCII码";
CM_ SG_ 2417552986 S2P_Cfg8_SW_Ver_Byte8_26 "CSC软件版本号Byte8对应的ASCII码";
CM_ SG_ 2417552987 S2P_Cfg8_SW_Ver_Byte1_27 "CSC软件版本号最低字节Byte1对应的ASCII码";
CM_ SG_ 2417552987 S2P_Cfg8_SW_Ver_Byte2_27 "CSC软件版本号Byte2对应的ASCII码";
CM_ SG_ 2417552987 S2P_Cfg8_SW_Ver_Byte3_27 "CSC软件版本号Byte3对应的ASCII码";
CM_ SG_ 2417552987 S2P_Cfg8_SW_Ver_Byte4_27 "CSC软件版本号Byte4对应的ASCII码";
CM_ SG_ 2417552987 S2P_Cfg8_SW_Ver_Byte5_27 "CSC软件版本号Byte5对应的ASCII码";
CM_ SG_ 2417552987 S2P_Cfg8_SW_Ver_Byte6_27 "CSC软件版本号Byte6对应的ASCII码";
CM_ SG_ 2417552987 S2P_Cfg8_SW_Ver_Byte7_27 "CSC软件版本号Byte7对应的ASCII码";
CM_ SG_ 2417552987 S2P_Cfg8_SW_Ver_Byte8_27 "CSC软件版本号Byte8对应的ASCII码";
CM_ SG_ 2417552988 S2P_Cfg8_SW_Ver_Byte1_28 "CSC软件版本号最低字节Byte1对应的ASCII码";
CM_ SG_ 2417552988 S2P_Cfg8_SW_Ver_Byte2_28 "CSC软件版本号Byte2对应的ASCII码";
CM_ SG_ 2417552988 S2P_Cfg8_SW_Ver_Byte3_28 "CSC软件版本号Byte3对应的ASCII码";
CM_ SG_ 2417552988 S2P_Cfg8_SW_Ver_Byte4_28 "CSC软件版本号Byte4对应的ASCII码";
CM_ SG_ 2417552988 S2P_Cfg8_SW_Ver_Byte5_28 "CSC软件版本号Byte5对应的ASCII码";
CM_ SG_ 2417552988 S2P_Cfg8_SW_Ver_Byte6_28 "CSC软件版本号Byte6对应的ASCII码";
CM_ SG_ 2417552988 S2P_Cfg8_SW_Ver_Byte7_28 "CSC软件版本号Byte7对应的ASCII码";
CM_ SG_ 2417552988 S2P_Cfg8_SW_Ver_Byte8_28 "CSC软件版本号Byte8对应的ASCII码";
CM_ SG_ 2417552989 S2P_Cfg8_SW_Ver_Byte1_29 "CSC软件版本号最低字节Byte1对应的ASCII码";
CM_ SG_ 2417552989 S2P_Cfg8_SW_Ver_Byte2_29 "CSC软件版本号Byte2对应的ASCII码";
CM_ SG_ 2417552989 S2P_Cfg8_SW_Ver_Byte3_29 "CSC软件版本号Byte3对应的ASCII码";
CM_ SG_ 2417552989 S2P_Cfg8_SW_Ver_Byte4_29 "CSC软件版本号Byte4对应的ASCII码";
CM_ SG_ 2417552989 S2P_Cfg8_SW_Ver_Byte5_29 "CSC软件版本号Byte5对应的ASCII码";
CM_ SG_ 2417552989 S2P_Cfg8_SW_Ver_Byte6_29 "CSC软件版本号Byte6对应的ASCII码";
CM_ SG_ 2417552989 S2P_Cfg8_SW_Ver_Byte7_29 "CSC软件版本号Byte7对应的ASCII码";
CM_ SG_ 2417552989 S2P_Cfg8_SW_Ver_Byte8_29 "CSC软件版本号Byte8对应的ASCII码";
CM_ SG_ 2417552990 S2P_Cfg8_SW_Ver_Byte1_30 "CSC软件版本号最低字节Byte1对应的ASCII码";
CM_ SG_ 2417552990 S2P_Cfg8_SW_Ver_Byte2_30 "CSC软件版本号Byte2对应的ASCII码";
CM_ SG_ 2417552990 S2P_Cfg8_SW_Ver_Byte3_30 "CSC软件版本号Byte3对应的ASCII码";
CM_ SG_ 2417552990 S2P_Cfg8_SW_Ver_Byte4_30 "CSC软件版本号Byte4对应的ASCII码";
CM_ SG_ 2417552990 S2P_Cfg8_SW_Ver_Byte5_30 "CSC软件版本号Byte5对应的ASCII码";
CM_ SG_ 2417552990 S2P_Cfg8_SW_Ver_Byte6_30 "CSC软件版本号Byte6对应的ASCII码";
CM_ SG_ 2417552990 S2P_Cfg8_SW_Ver_Byte7_30 "CSC软件版本号Byte7对应的ASCII码";
CM_ SG_ 2417552990 S2P_Cfg8_SW_Ver_Byte8_30 "CSC软件版本号Byte8对应的ASCII码";
CM_ SG_ 2417552991 S2P_Cfg8_SW_Ver_Byte1_31 "CSC软件版本号最低字节Byte1对应的ASCII码";
CM_ SG_ 2417552991 S2P_Cfg8_SW_Ver_Byte2_31 "CSC软件版本号Byte2对应的ASCII码";
CM_ SG_ 2417552991 S2P_Cfg8_SW_Ver_Byte3_31 "CSC软件版本号Byte3对应的ASCII码";
CM_ SG_ 2417552991 S2P_Cfg8_SW_Ver_Byte4_31 "CSC软件版本号Byte4对应的ASCII码";
CM_ SG_ 2417552991 S2P_Cfg8_SW_Ver_Byte5_31 "CSC软件版本号Byte5对应的ASCII码";
CM_ SG_ 2417552991 S2P_Cfg8_SW_Ver_Byte6_31 "CSC软件版本号Byte6对应的ASCII码";
CM_ SG_ 2417552991 S2P_Cfg8_SW_Ver_Byte7_31 "CSC软件版本号Byte7对应的ASCII码";
CM_ SG_ 2417552991 S2P_Cfg8_SW_Ver_Byte8_31 "CSC软件版本号Byte8对应的ASCII码";
CM_ SG_ 2417552992 S2P_Cfg8_SW_Ver_Byte1_32 "CSC软件版本号最低字节Byte1对应的ASCII码";
CM_ SG_ 2417552992 S2P_Cfg8_SW_Ver_Byte2_32 "CSC软件版本号Byte2对应的ASCII码";
CM_ SG_ 2417552992 S2P_Cfg8_SW_Ver_Byte3_32 "CSC软件版本号Byte3对应的ASCII码";
CM_ SG_ 2417552992 S2P_Cfg8_SW_Ver_Byte4_32 "CSC软件版本号Byte4对应的ASCII码";
CM_ SG_ 2417552992 S2P_Cfg8_SW_Ver_Byte5_32 "CSC软件版本号Byte5对应的ASCII码";
CM_ SG_ 2417552992 S2P_Cfg8_SW_Ver_Byte6_32 "CSC软件版本号Byte6对应的ASCII码";
CM_ SG_ 2417552992 S2P_Cfg8_SW_Ver_Byte7_32 "CSC软件版本号Byte7对应的ASCII码";
CM_ SG_ 2417552992 S2P_Cfg8_SW_Ver_Byte8_32 "CSC软件版本号Byte8对应的ASCII码";
CM_ SG_ 2417552993 S2P_Cfg8_SW_Ver_Byte1_33 "CSC软件版本号最低字节Byte1对应的ASCII码";
CM_ SG_ 2417552993 S2P_Cfg8_SW_Ver_Byte2_33 "CSC软件版本号Byte2对应的ASCII码";
CM_ SG_ 2417552993 S2P_Cfg8_SW_Ver_Byte3_33 "CSC软件版本号Byte3对应的ASCII码";
CM_ SG_ 2417552993 S2P_Cfg8_SW_Ver_Byte4_33 "CSC软件版本号Byte4对应的ASCII码";
CM_ SG_ 2417552993 S2P_Cfg8_SW_Ver_Byte5_33 "CSC软件版本号Byte5对应的ASCII码";
CM_ SG_ 2417552993 S2P_Cfg8_SW_Ver_Byte6_33 "CSC软件版本号Byte6对应的ASCII码";
CM_ SG_ 2417552993 S2P_Cfg8_SW_Ver_Byte7_33 "CSC软件版本号Byte7对应的ASCII码";
CM_ SG_ 2417552993 S2P_Cfg8_SW_Ver_Byte8_33 "CSC软件版本号Byte8对应的ASCII码";
CM_ SG_ 2417552994 S2P_Cfg8_SW_Ver_Byte1_34 "CSC软件版本号最低字节Byte1对应的ASCII码";
CM_ SG_ 2417552994 S2P_Cfg8_SW_Ver_Byte2_34 "CSC软件版本号Byte2对应的ASCII码";
CM_ SG_ 2417552994 S2P_Cfg8_SW_Ver_Byte3_34 "CSC软件版本号Byte3对应的ASCII码";
CM_ SG_ 2417552994 S2P_Cfg8_SW_Ver_Byte4_34 "CSC软件版本号Byte4对应的ASCII码";
CM_ SG_ 2417552994 S2P_Cfg8_SW_Ver_Byte5_34 "CSC软件版本号Byte5对应的ASCII码";
CM_ SG_ 2417552994 S2P_Cfg8_SW_Ver_Byte6_34 "CSC软件版本号Byte6对应的ASCII码";
CM_ SG_ 2417552994 S2P_Cfg8_SW_Ver_Byte7_34 "CSC软件版本号Byte7对应的ASCII码";
CM_ SG_ 2417552994 S2P_Cfg8_SW_Ver_Byte8_34 "CSC软件版本号Byte8对应的ASCII码";
CM_ SG_ 2417552995 S2P_Cfg8_SW_Ver_Byte1_35 "CSC软件版本号最低字节Byte1对应的ASCII码";
CM_ SG_ 2417552995 S2P_Cfg8_SW_Ver_Byte2_35 "CSC软件版本号Byte2对应的ASCII码";
CM_ SG_ 2417552995 S2P_Cfg8_SW_Ver_Byte3_35 "CSC软件版本号Byte3对应的ASCII码";
CM_ SG_ 2417552995 S2P_Cfg8_SW_Ver_Byte4_35 "CSC软件版本号Byte4对应的ASCII码";
CM_ SG_ 2417552995 S2P_Cfg8_SW_Ver_Byte5_35 "CSC软件版本号Byte5对应的ASCII码";
CM_ SG_ 2417552995 S2P_Cfg8_SW_Ver_Byte6_35 "CSC软件版本号Byte6对应的ASCII码";
CM_ SG_ 2417552995 S2P_Cfg8_SW_Ver_Byte7_35 "CSC软件版本号Byte7对应的ASCII码";
CM_ SG_ 2417552995 S2P_Cfg8_SW_Ver_Byte8_35 "CSC软件版本号Byte8对应的ASCII码";
CM_ SG_ 2417552996 S2P_Cfg8_SW_Ver_Byte1_36 "CSC软件版本号最低字节Byte1对应的ASCII码";
CM_ SG_ 2417552996 S2P_Cfg8_SW_Ver_Byte2_36 "CSC软件版本号Byte2对应的ASCII码";
CM_ SG_ 2417552996 S2P_Cfg8_SW_Ver_Byte3_36 "CSC软件版本号Byte3对应的ASCII码";
CM_ SG_ 2417552996 S2P_Cfg8_SW_Ver_Byte4_36 "CSC软件版本号Byte4对应的ASCII码";
CM_ SG_ 2417552996 S2P_Cfg8_SW_Ver_Byte5_36 "CSC软件版本号Byte5对应的ASCII码";
CM_ SG_ 2417552996 S2P_Cfg8_SW_Ver_Byte6_36 "CSC软件版本号Byte6对应的ASCII码";
CM_ SG_ 2417552996 S2P_Cfg8_SW_Ver_Byte7_36 "CSC软件版本号Byte7对应的ASCII码";
CM_ SG_ 2417552996 S2P_Cfg8_SW_Ver_Byte8_36 "CSC软件版本号Byte8对应的ASCII码";
CM_ SG_ 2417552997 S2P_Cfg8_SW_Ver_Byte1_37 "CSC软件版本号最低字节Byte1对应的ASCII码";
CM_ SG_ 2417552997 S2P_Cfg8_SW_Ver_Byte2_37 "CSC软件版本号Byte2对应的ASCII码";
CM_ SG_ 2417552997 S2P_Cfg8_SW_Ver_Byte3_37 "CSC软件版本号Byte3对应的ASCII码";
CM_ SG_ 2417552997 S2P_Cfg8_SW_Ver_Byte4_37 "CSC软件版本号Byte4对应的ASCII码";
CM_ SG_ 2417552997 S2P_Cfg8_SW_Ver_Byte5_37 "CSC软件版本号Byte5对应的ASCII码";
CM_ SG_ 2417552997 S2P_Cfg8_SW_Ver_Byte6_37 "CSC软件版本号Byte6对应的ASCII码";
CM_ SG_ 2417552997 S2P_Cfg8_SW_Ver_Byte7_37 "CSC软件版本号Byte7对应的ASCII码";
CM_ SG_ 2417552997 S2P_Cfg8_SW_Ver_Byte8_37 "CSC软件版本号Byte8对应的ASCII码";
CM_ SG_ 2417552998 S2P_Cfg8_SW_Ver_Byte1_38 "CSC软件版本号最低字节Byte1对应的ASCII码";
CM_ SG_ 2417552998 S2P_Cfg8_SW_Ver_Byte2_38 "CSC软件版本号Byte2对应的ASCII码";
CM_ SG_ 2417552998 S2P_Cfg8_SW_Ver_Byte3_38 "CSC软件版本号Byte3对应的ASCII码";
CM_ SG_ 2417552998 S2P_Cfg8_SW_Ver_Byte4_38 "CSC软件版本号Byte4对应的ASCII码";
CM_ SG_ 2417552998 S2P_Cfg8_SW_Ver_Byte5_38 "CSC软件版本号Byte5对应的ASCII码";
CM_ SG_ 2417552998 S2P_Cfg8_SW_Ver_Byte6_38 "CSC软件版本号Byte6对应的ASCII码";
CM_ SG_ 2417552998 S2P_Cfg8_SW_Ver_Byte7_38 "CSC软件版本号Byte7对应的ASCII码";
CM_ SG_ 2417552998 S2P_Cfg8_SW_Ver_Byte8_38 "CSC软件版本号Byte8对应的ASCII码";
CM_ SG_ 2417552999 S2P_Cfg8_SW_Ver_Byte1_39 "CSC软件版本号最低字节Byte1对应的ASCII码";
CM_ SG_ 2417552999 S2P_Cfg8_SW_Ver_Byte2_39 "CSC软件版本号Byte2对应的ASCII码";
CM_ SG_ 2417552999 S2P_Cfg8_SW_Ver_Byte3_39 "CSC软件版本号Byte3对应的ASCII码";
CM_ SG_ 2417552999 S2P_Cfg8_SW_Ver_Byte4_39 "CSC软件版本号Byte4对应的ASCII码";
CM_ SG_ 2417552999 S2P_Cfg8_SW_Ver_Byte5_39 "CSC软件版本号Byte5对应的ASCII码";
CM_ SG_ 2417552999 S2P_Cfg8_SW_Ver_Byte6_39 "CSC软件版本号Byte6对应的ASCII码";
CM_ SG_ 2417552999 S2P_Cfg8_SW_Ver_Byte7_39 "CSC软件版本号Byte7对应的ASCII码";
CM_ SG_ 2417552999 S2P_Cfg8_SW_Ver_Byte8_39 "CSC软件版本号Byte8对应的ASCII码";
CM_ SG_ 2417553000 S2P_Cfg8_SW_Ver_Byte1_40 "CSC软件版本号最低字节Byte1对应的ASCII码";
CM_ SG_ 2417553000 S2P_Cfg8_SW_Ver_Byte2_40 "CSC软件版本号Byte2对应的ASCII码";
CM_ SG_ 2417553000 S2P_Cfg8_SW_Ver_Byte3_40 "CSC软件版本号Byte3对应的ASCII码";
CM_ SG_ 2417553000 S2P_Cfg8_SW_Ver_Byte4_40 "CSC软件版本号Byte4对应的ASCII码";
CM_ SG_ 2417553000 S2P_Cfg8_SW_Ver_Byte5_40 "CSC软件版本号Byte5对应的ASCII码";
CM_ SG_ 2417553000 S2P_Cfg8_SW_Ver_Byte6_40 "CSC软件版本号Byte6对应的ASCII码";
CM_ SG_ 2417553000 S2P_Cfg8_SW_Ver_Byte7_40 "CSC软件版本号Byte7对应的ASCII码";
CM_ SG_ 2417553000 S2P_Cfg8_SW_Ver_Byte8_40 "CSC软件版本号Byte8对应的ASCII码";
CM_ SG_ 2417553001 S2P_Cfg8_SW_Ver_Byte1_41 "CSC软件版本号最低字节Byte1对应的ASCII码";
CM_ SG_ 2417553001 S2P_Cfg8_SW_Ver_Byte2_41 "CSC软件版本号Byte2对应的ASCII码";
CM_ SG_ 2417553001 S2P_Cfg8_SW_Ver_Byte3_41 "CSC软件版本号Byte3对应的ASCII码";
CM_ SG_ 2417553001 S2P_Cfg8_SW_Ver_Byte4_41 "CSC软件版本号Byte4对应的ASCII码";
CM_ SG_ 2417553001 S2P_Cfg8_SW_Ver_Byte5_41 "CSC软件版本号Byte5对应的ASCII码";
CM_ SG_ 2417553001 S2P_Cfg8_SW_Ver_Byte6_41 "CSC软件版本号Byte6对应的ASCII码";
CM_ SG_ 2417553001 S2P_Cfg8_SW_Ver_Byte7_41 "CSC软件版本号Byte7对应的ASCII码";
CM_ SG_ 2417553001 S2P_Cfg8_SW_Ver_Byte8_41 "CSC软件版本号Byte8对应的ASCII码";
CM_ SG_ 2417553002 S2P_Cfg8_SW_Ver_Byte1_42 "CSC软件版本号最低字节Byte1对应的ASCII码";
CM_ SG_ 2417553002 S2P_Cfg8_SW_Ver_Byte2_42 "CSC软件版本号Byte2对应的ASCII码";
CM_ SG_ 2417553002 S2P_Cfg8_SW_Ver_Byte3_42 "CSC软件版本号Byte3对应的ASCII码";
CM_ SG_ 2417553002 S2P_Cfg8_SW_Ver_Byte4_42 "CSC软件版本号Byte4对应的ASCII码";
CM_ SG_ 2417553002 S2P_Cfg8_SW_Ver_Byte5_42 "CSC软件版本号Byte5对应的ASCII码";
CM_ SG_ 2417553002 S2P_Cfg8_SW_Ver_Byte6_42 "CSC软件版本号Byte6对应的ASCII码";
CM_ SG_ 2417553002 S2P_Cfg8_SW_Ver_Byte7_42 "CSC软件版本号Byte7对应的ASCII码";
CM_ SG_ 2417553002 S2P_Cfg8_SW_Ver_Byte8_42 "CSC软件版本号Byte8对应的ASCII码";
CM_ SG_ 2417553003 S2P_Cfg8_SW_Ver_Byte1_43 "CSC软件版本号最低字节Byte1对应的ASCII码";
CM_ SG_ 2417553003 S2P_Cfg8_SW_Ver_Byte2_43 "CSC软件版本号Byte2对应的ASCII码";
CM_ SG_ 2417553003 S2P_Cfg8_SW_Ver_Byte3_43 "CSC软件版本号Byte3对应的ASCII码";
CM_ SG_ 2417553003 S2P_Cfg8_SW_Ver_Byte4_43 "CSC软件版本号Byte4对应的ASCII码";
CM_ SG_ 2417553003 S2P_Cfg8_SW_Ver_Byte5_43 "CSC软件版本号Byte5对应的ASCII码";
CM_ SG_ 2417553003 S2P_Cfg8_SW_Ver_Byte6_43 "CSC软件版本号Byte6对应的ASCII码";
CM_ SG_ 2417553003 S2P_Cfg8_SW_Ver_Byte7_43 "CSC软件版本号Byte7对应的ASCII码";
CM_ SG_ 2417553003 S2P_Cfg8_SW_Ver_Byte8_43 "CSC软件版本号Byte8对应的ASCII码";
CM_ SG_ 2417553004 S2P_Cfg8_SW_Ver_Byte1_44 "CSC软件版本号最低字节Byte1对应的ASCII码";
CM_ SG_ 2417553004 S2P_Cfg8_SW_Ver_Byte2_44 "CSC软件版本号Byte2对应的ASCII码";
CM_ SG_ 2417553004 S2P_Cfg8_SW_Ver_Byte3_44 "CSC软件版本号Byte3对应的ASCII码";
CM_ SG_ 2417553004 S2P_Cfg8_SW_Ver_Byte4_44 "CSC软件版本号Byte4对应的ASCII码";
CM_ SG_ 2417553004 S2P_Cfg8_SW_Ver_Byte5_44 "CSC软件版本号Byte5对应的ASCII码";
CM_ SG_ 2417553004 S2P_Cfg8_SW_Ver_Byte6_44 "CSC软件版本号Byte6对应的ASCII码";
CM_ SG_ 2417553004 S2P_Cfg8_SW_Ver_Byte7_44 "CSC软件版本号Byte7对应的ASCII码";
CM_ SG_ 2417553004 S2P_Cfg8_SW_Ver_Byte8_44 "CSC软件版本号Byte8对应的ASCII码";
CM_ SG_ 2417553005 S2P_Cfg8_SW_Ver_Byte1_45 "CSC软件版本号最低字节Byte1对应的ASCII码";
CM_ SG_ 2417553005 S2P_Cfg8_SW_Ver_Byte2_45 "CSC软件版本号Byte2对应的ASCII码";
CM_ SG_ 2417553005 S2P_Cfg8_SW_Ver_Byte3_45 "CSC软件版本号Byte3对应的ASCII码";
CM_ SG_ 2417553005 S2P_Cfg8_SW_Ver_Byte4_45 "CSC软件版本号Byte4对应的ASCII码";
CM_ SG_ 2417553005 S2P_Cfg8_SW_Ver_Byte5_45 "CSC软件版本号Byte5对应的ASCII码";
CM_ SG_ 2417553005 S2P_Cfg8_SW_Ver_Byte6_45 "CSC软件版本号Byte6对应的ASCII码";
CM_ SG_ 2417553005 S2P_Cfg8_SW_Ver_Byte7_45 "CSC软件版本号Byte7对应的ASCII码";
CM_ SG_ 2417553005 S2P_Cfg8_SW_Ver_Byte8_45 "CSC软件版本号Byte8对应的ASCII码";
CM_ SG_ 2417553006 S2P_Cfg8_SW_Ver_Byte1_46 "CSC软件版本号最低字节Byte1对应的ASCII码";
CM_ SG_ 2417553006 S2P_Cfg8_SW_Ver_Byte2_46 "CSC软件版本号Byte2对应的ASCII码";
CM_ SG_ 2417553006 S2P_Cfg8_SW_Ver_Byte3_46 "CSC软件版本号Byte3对应的ASCII码";
CM_ SG_ 2417553006 S2P_Cfg8_SW_Ver_Byte4_46 "CSC软件版本号Byte4对应的ASCII码";
CM_ SG_ 2417553006 S2P_Cfg8_SW_Ver_Byte5_46 "CSC软件版本号Byte5对应的ASCII码";
CM_ SG_ 2417553006 S2P_Cfg8_SW_Ver_Byte6_46 "CSC软件版本号Byte6对应的ASCII码";
CM_ SG_ 2417553006 S2P_Cfg8_SW_Ver_Byte7_46 "CSC软件版本号Byte7对应的ASCII码";
CM_ SG_ 2417553006 S2P_Cfg8_SW_Ver_Byte8_46 "CSC软件版本号Byte8对应的ASCII码";
CM_ SG_ 2417553007 S2P_Cfg8_SW_Ver_Byte1_47 "CSC软件版本号最低字节Byte1对应的ASCII码";
CM_ SG_ 2417553007 S2P_Cfg8_SW_Ver_Byte2_47 "CSC软件版本号Byte2对应的ASCII码";
CM_ SG_ 2417553007 S2P_Cfg8_SW_Ver_Byte3_47 "CSC软件版本号Byte3对应的ASCII码";
CM_ SG_ 2417553007 S2P_Cfg8_SW_Ver_Byte4_47 "CSC软件版本号Byte4对应的ASCII码";
CM_ SG_ 2417553007 S2P_Cfg8_SW_Ver_Byte5_47 "CSC软件版本号Byte5对应的ASCII码";
CM_ SG_ 2417553007 S2P_Cfg8_SW_Ver_Byte6_47 "CSC软件版本号Byte6对应的ASCII码";
CM_ SG_ 2417553007 S2P_Cfg8_SW_Ver_Byte7_47 "CSC软件版本号Byte7对应的ASCII码";
CM_ SG_ 2417553007 S2P_Cfg8_SW_Ver_Byte8_47 "CSC软件版本号Byte8对应的ASCII码";
CM_ SG_ 2417553008 S2P_Cfg8_SW_Ver_Byte1_48 "CSC软件版本号最低字节Byte1对应的ASCII码";
CM_ SG_ 2417553008 S2P_Cfg8_SW_Ver_Byte2_48 "CSC软件版本号Byte2对应的ASCII码";
CM_ SG_ 2417553008 S2P_Cfg8_SW_Ver_Byte3_48 "CSC软件版本号Byte3对应的ASCII码";
CM_ SG_ 2417553008 S2P_Cfg8_SW_Ver_Byte4_48 "CSC软件版本号Byte4对应的ASCII码";
CM_ SG_ 2417553008 S2P_Cfg8_SW_Ver_Byte5_48 "CSC软件版本号Byte5对应的ASCII码";
CM_ SG_ 2417553008 S2P_Cfg8_SW_Ver_Byte6_48 "CSC软件版本号Byte6对应的ASCII码";
CM_ SG_ 2417553008 S2P_Cfg8_SW_Ver_Byte7_48 "CSC软件版本号Byte7对应的ASCII码";
CM_ SG_ 2417553008 S2P_Cfg8_SW_Ver_Byte8_48 "CSC软件版本号Byte8对应的ASCII码";
CM_ SG_ 2417553009 S2P_Cfg8_SW_Ver_Byte1_49 "CSC软件版本号最低字节Byte1对应的ASCII码";
CM_ SG_ 2417553009 S2P_Cfg8_SW_Ver_Byte2_49 "CSC软件版本号Byte2对应的ASCII码";
CM_ SG_ 2417553009 S2P_Cfg8_SW_Ver_Byte3_49 "CSC软件版本号Byte3对应的ASCII码";
CM_ SG_ 2417553009 S2P_Cfg8_SW_Ver_Byte4_49 "CSC软件版本号Byte4对应的ASCII码";
CM_ SG_ 2417553009 S2P_Cfg8_SW_Ver_Byte5_49 "CSC软件版本号Byte5对应的ASCII码";
CM_ SG_ 2417553009 S2P_Cfg8_SW_Ver_Byte6_49 "CSC软件版本号Byte6对应的ASCII码";
CM_ SG_ 2417553009 S2P_Cfg8_SW_Ver_Byte7_49 "CSC软件版本号Byte7对应的ASCII码";
CM_ SG_ 2417553009 S2P_Cfg8_SW_Ver_Byte8_49 "CSC软件版本号Byte8对应的ASCII码";
CM_ SG_ 2417553010 S2P_Cfg8_SW_Ver_Byte1_50 "CSC软件版本号最低字节Byte1对应的ASCII码";
CM_ SG_ 2417553010 S2P_Cfg8_SW_Ver_Byte2_50 "CSC软件版本号Byte2对应的ASCII码";
CM_ SG_ 2417553010 S2P_Cfg8_SW_Ver_Byte3_50 "CSC软件版本号Byte3对应的ASCII码";
CM_ SG_ 2417553010 S2P_Cfg8_SW_Ver_Byte4_50 "CSC软件版本号Byte4对应的ASCII码";
CM_ SG_ 2417553010 S2P_Cfg8_SW_Ver_Byte5_50 "CSC软件版本号Byte5对应的ASCII码";
CM_ SG_ 2417553010 S2P_Cfg8_SW_Ver_Byte6_50 "CSC软件版本号Byte6对应的ASCII码";
CM_ SG_ 2417553010 S2P_Cfg8_SW_Ver_Byte7_50 "CSC软件版本号Byte7对应的ASCII码";
CM_ SG_ 2417553010 S2P_Cfg8_SW_Ver_Byte8_50 "CSC软件版本号Byte8对应的ASCII码";
CM_ SG_ 2417553011 S2P_Cfg8_SW_Ver_Byte1_51 "CSC软件版本号最低字节Byte1对应的ASCII码";
CM_ SG_ 2417553011 S2P_Cfg8_SW_Ver_Byte2_51 "CSC软件版本号Byte2对应的ASCII码";
CM_ SG_ 2417553011 S2P_Cfg8_SW_Ver_Byte3_51 "CSC软件版本号Byte3对应的ASCII码";
CM_ SG_ 2417553011 S2P_Cfg8_SW_Ver_Byte4_51 "CSC软件版本号Byte4对应的ASCII码";
CM_ SG_ 2417553011 S2P_Cfg8_SW_Ver_Byte5_51 "CSC软件版本号Byte5对应的ASCII码";
CM_ SG_ 2417553011 S2P_Cfg8_SW_Ver_Byte6_51 "CSC软件版本号Byte6对应的ASCII码";
CM_ SG_ 2417553011 S2P_Cfg8_SW_Ver_Byte7_51 "CSC软件版本号Byte7对应的ASCII码";
CM_ SG_ 2417553011 S2P_Cfg8_SW_Ver_Byte8_51 "CSC软件版本号Byte8对应的ASCII码";
CM_ SG_ 2417553012 S2P_Cfg8_SW_Ver_Byte1_52 "CSC软件版本号最低字节Byte1对应的ASCII码";
CM_ SG_ 2417553012 S2P_Cfg8_SW_Ver_Byte2_52 "CSC软件版本号Byte2对应的ASCII码";
CM_ SG_ 2417553012 S2P_Cfg8_SW_Ver_Byte3_52 "CSC软件版本号Byte3对应的ASCII码";
CM_ SG_ 2417553012 S2P_Cfg8_SW_Ver_Byte4_52 "CSC软件版本号Byte4对应的ASCII码";
CM_ SG_ 2417553012 S2P_Cfg8_SW_Ver_Byte5_52 "CSC软件版本号Byte5对应的ASCII码";
CM_ SG_ 2417553012 S2P_Cfg8_SW_Ver_Byte6_52 "CSC软件版本号Byte6对应的ASCII码";
CM_ SG_ 2417553012 S2P_Cfg8_SW_Ver_Byte7_52 "CSC软件版本号Byte7对应的ASCII码";
CM_ SG_ 2417553012 S2P_Cfg8_SW_Ver_Byte8_52 "CSC软件版本号Byte8对应的ASCII码";
CM_ SG_ 2417553013 S2P_Cfg8_SW_Ver_Byte1_53 "CSC软件版本号最低字节Byte1对应的ASCII码";
CM_ SG_ 2417553013 S2P_Cfg8_SW_Ver_Byte2_53 "CSC软件版本号Byte2对应的ASCII码";
CM_ SG_ 2417553013 S2P_Cfg8_SW_Ver_Byte3_53 "CSC软件版本号Byte3对应的ASCII码";
CM_ SG_ 2417553013 S2P_Cfg8_SW_Ver_Byte4_53 "CSC软件版本号Byte4对应的ASCII码";
CM_ SG_ 2417553013 S2P_Cfg8_SW_Ver_Byte5_53 "CSC软件版本号Byte5对应的ASCII码";
CM_ SG_ 2417553013 S2P_Cfg8_SW_Ver_Byte6_53 "CSC软件版本号Byte6对应的ASCII码";
CM_ SG_ 2417553013 S2P_Cfg8_SW_Ver_Byte7_53 "CSC软件版本号Byte7对应的ASCII码";
CM_ SG_ 2417553013 S2P_Cfg8_SW_Ver_Byte8_53 "CSC软件版本号Byte8对应的ASCII码";
CM_ SG_ 2417553014 S2P_Cfg8_SW_Ver_Byte1_54 "CSC软件版本号最低字节Byte1对应的ASCII码";
CM_ SG_ 2417553014 S2P_Cfg8_SW_Ver_Byte2_54 "CSC软件版本号Byte2对应的ASCII码";
CM_ SG_ 2417553014 S2P_Cfg8_SW_Ver_Byte3_54 "CSC软件版本号Byte3对应的ASCII码";
CM_ SG_ 2417553014 S2P_Cfg8_SW_Ver_Byte4_54 "CSC软件版本号Byte4对应的ASCII码";
CM_ SG_ 2417553014 S2P_Cfg8_SW_Ver_Byte5_54 "CSC软件版本号Byte5对应的ASCII码";
CM_ SG_ 2417553014 S2P_Cfg8_SW_Ver_Byte6_54 "CSC软件版本号Byte6对应的ASCII码";
CM_ SG_ 2417553014 S2P_Cfg8_SW_Ver_Byte7_54 "CSC软件版本号Byte7对应的ASCII码";
CM_ SG_ 2417553014 S2P_Cfg8_SW_Ver_Byte8_54 "CSC软件版本号Byte8对应的ASCII码";
CM_ SG_ 2417553015 S2P_Cfg8_SW_Ver_Byte1_55 "CSC软件版本号最低字节Byte1对应的ASCII码";
CM_ SG_ 2417553015 S2P_Cfg8_SW_Ver_Byte2_55 "CSC软件版本号Byte2对应的ASCII码";
CM_ SG_ 2417553015 S2P_Cfg8_SW_Ver_Byte3_55 "CSC软件版本号Byte3对应的ASCII码";
CM_ SG_ 2417553015 S2P_Cfg8_SW_Ver_Byte4_55 "CSC软件版本号Byte4对应的ASCII码";
CM_ SG_ 2417553015 S2P_Cfg8_SW_Ver_Byte5_55 "CSC软件版本号Byte5对应的ASCII码";
CM_ SG_ 2417553015 S2P_Cfg8_SW_Ver_Byte6_55 "CSC软件版本号Byte6对应的ASCII码";
CM_ SG_ 2417553015 S2P_Cfg8_SW_Ver_Byte7_55 "CSC软件版本号Byte7对应的ASCII码";
CM_ SG_ 2417553015 S2P_Cfg8_SW_Ver_Byte8_55 "CSC软件版本号Byte8对应的ASCII码";
CM_ SG_ 2417553016 S2P_Cfg8_SW_Ver_Byte1_56 "CSC软件版本号最低字节Byte1对应的ASCII码";
CM_ SG_ 2417553016 S2P_Cfg8_SW_Ver_Byte2_56 "CSC软件版本号Byte2对应的ASCII码";
CM_ SG_ 2417553016 S2P_Cfg8_SW_Ver_Byte3_56 "CSC软件版本号Byte3对应的ASCII码";
CM_ SG_ 2417553016 S2P_Cfg8_SW_Ver_Byte4_56 "CSC软件版本号Byte4对应的ASCII码";
CM_ SG_ 2417553016 S2P_Cfg8_SW_Ver_Byte5_56 "CSC软件版本号Byte5对应的ASCII码";
CM_ SG_ 2417553016 S2P_Cfg8_SW_Ver_Byte6_56 "CSC软件版本号Byte6对应的ASCII码";
CM_ SG_ 2417553016 S2P_Cfg8_SW_Ver_Byte7_56 "CSC软件版本号Byte7对应的ASCII码";
CM_ SG_ 2417553016 S2P_Cfg8_SW_Ver_Byte8_56 "CSC软件版本号Byte8对应的ASCII码";
CM_ SG_ 2417553017 S2P_Cfg8_SW_Ver_Byte1_57 "CSC软件版本号最低字节Byte1对应的ASCII码";
CM_ SG_ 2417553017 S2P_Cfg8_SW_Ver_Byte2_57 "CSC软件版本号Byte2对应的ASCII码";
CM_ SG_ 2417553017 S2P_Cfg8_SW_Ver_Byte3_57 "CSC软件版本号Byte3对应的ASCII码";
CM_ SG_ 2417553017 S2P_Cfg8_SW_Ver_Byte4_57 "CSC软件版本号Byte4对应的ASCII码";
CM_ SG_ 2417553017 S2P_Cfg8_SW_Ver_Byte5_57 "CSC软件版本号Byte5对应的ASCII码";
CM_ SG_ 2417553017 S2P_Cfg8_SW_Ver_Byte6_57 "CSC软件版本号Byte6对应的ASCII码";
CM_ SG_ 2417553017 S2P_Cfg8_SW_Ver_Byte7_57 "CSC软件版本号Byte7对应的ASCII码";
CM_ SG_ 2417553017 S2P_Cfg8_SW_Ver_Byte8_57 "CSC软件版本号Byte8对应的ASCII码";
CM_ SG_ 2417553018 S2P_Cfg8_SW_Ver_Byte1_58 "CSC软件版本号最低字节Byte1对应的ASCII码";
CM_ SG_ 2417553018 S2P_Cfg8_SW_Ver_Byte2_58 "CSC软件版本号Byte2对应的ASCII码";
CM_ SG_ 2417553018 S2P_Cfg8_SW_Ver_Byte3_58 "CSC软件版本号Byte3对应的ASCII码";
CM_ SG_ 2417553018 S2P_Cfg8_SW_Ver_Byte4_58 "CSC软件版本号Byte4对应的ASCII码";
CM_ SG_ 2417553018 S2P_Cfg8_SW_Ver_Byte5_58 "CSC软件版本号Byte5对应的ASCII码";
CM_ SG_ 2417553018 S2P_Cfg8_SW_Ver_Byte6_58 "CSC软件版本号Byte6对应的ASCII码";
CM_ SG_ 2417553018 S2P_Cfg8_SW_Ver_Byte7_58 "CSC软件版本号Byte7对应的ASCII码";
CM_ SG_ 2417553018 S2P_Cfg8_SW_Ver_Byte8_58 "CSC软件版本号Byte8对应的ASCII码";
CM_ SG_ 2417553019 S2P_Cfg8_SW_Ver_Byte1_59 "CSC软件版本号最低字节Byte1对应的ASCII码";
CM_ SG_ 2417553019 S2P_Cfg8_SW_Ver_Byte2_59 "CSC软件版本号Byte2对应的ASCII码";
CM_ SG_ 2417553019 S2P_Cfg8_SW_Ver_Byte3_59 "CSC软件版本号Byte3对应的ASCII码";
CM_ SG_ 2417553019 S2P_Cfg8_SW_Ver_Byte4_59 "CSC软件版本号Byte4对应的ASCII码";
CM_ SG_ 2417553019 S2P_Cfg8_SW_Ver_Byte5_59 "CSC软件版本号Byte5对应的ASCII码";
CM_ SG_ 2417553019 S2P_Cfg8_SW_Ver_Byte6_59 "CSC软件版本号Byte6对应的ASCII码";
CM_ SG_ 2417553019 S2P_Cfg8_SW_Ver_Byte7_59 "CSC软件版本号Byte7对应的ASCII码";
CM_ SG_ 2417553019 S2P_Cfg8_SW_Ver_Byte8_59 "CSC软件版本号Byte8对应的ASCII码";
CM_ SG_ 2417553020 S2P_Cfg8_SW_Ver_Byte1_60 "CSC软件版本号最低字节Byte1对应的ASCII码";
CM_ SG_ 2417553020 S2P_Cfg8_SW_Ver_Byte2_60 "CSC软件版本号Byte2对应的ASCII码";
CM_ SG_ 2417553020 S2P_Cfg8_SW_Ver_Byte3_60 "CSC软件版本号Byte3对应的ASCII码";
CM_ SG_ 2417553020 S2P_Cfg8_SW_Ver_Byte4_60 "CSC软件版本号Byte4对应的ASCII码";
CM_ SG_ 2417553020 S2P_Cfg8_SW_Ver_Byte5_60 "CSC软件版本号Byte5对应的ASCII码";
CM_ SG_ 2417553020 S2P_Cfg8_SW_Ver_Byte6_60 "CSC软件版本号Byte6对应的ASCII码";
CM_ SG_ 2417553020 S2P_Cfg8_SW_Ver_Byte7_60 "CSC软件版本号Byte7对应的ASCII码";
CM_ SG_ 2417553020 S2P_Cfg8_SW_Ver_Byte8_60 "CSC软件版本号Byte8对应的ASCII码";
CM_ SG_ 2417553021 S2P_Cfg8_SW_Ver_Byte1_61 "CSC软件版本号最低字节Byte1对应的ASCII码";
CM_ SG_ 2417553021 S2P_Cfg8_SW_Ver_Byte2_61 "CSC软件版本号Byte2对应的ASCII码";
CM_ SG_ 2417553021 S2P_Cfg8_SW_Ver_Byte3_61 "CSC软件版本号Byte3对应的ASCII码";
CM_ SG_ 2417553021 S2P_Cfg8_SW_Ver_Byte4_61 "CSC软件版本号Byte4对应的ASCII码";
CM_ SG_ 2417553021 S2P_Cfg8_SW_Ver_Byte5_61 "CSC软件版本号Byte5对应的ASCII码";
CM_ SG_ 2417553021 S2P_Cfg8_SW_Ver_Byte6_61 "CSC软件版本号Byte6对应的ASCII码";
CM_ SG_ 2417553021 S2P_Cfg8_SW_Ver_Byte7_61 "CSC软件版本号Byte7对应的ASCII码";
CM_ SG_ 2417553021 S2P_Cfg8_SW_Ver_Byte8_61 "CSC软件版本号Byte8对应的ASCII码";
CM_ SG_ 2417553022 S2P_Cfg8_SW_Ver_Byte1_62 "CSC软件版本号最低字节Byte1对应的ASCII码";
CM_ SG_ 2417553022 S2P_Cfg8_SW_Ver_Byte2_62 "CSC软件版本号Byte2对应的ASCII码";
CM_ SG_ 2417553022 S2P_Cfg8_SW_Ver_Byte3_62 "CSC软件版本号Byte3对应的ASCII码";
CM_ SG_ 2417553022 S2P_Cfg8_SW_Ver_Byte4_62 "CSC软件版本号Byte4对应的ASCII码";
CM_ SG_ 2417553022 S2P_Cfg8_SW_Ver_Byte5_62 "CSC软件版本号Byte5对应的ASCII码";
CM_ SG_ 2417553022 S2P_Cfg8_SW_Ver_Byte6_62 "CSC软件版本号Byte6对应的ASCII码";
CM_ SG_ 2417553022 S2P_Cfg8_SW_Ver_Byte7_62 "CSC软件版本号Byte7对应的ASCII码";
CM_ SG_ 2417553022 S2P_Cfg8_SW_Ver_Byte8_62 "CSC软件版本号Byte8对应的ASCII码";
CM_ SG_ 2417553023 S2P_Cfg8_SW_Ver_Byte1_63 "CSC软件版本号最低字节Byte1对应的ASCII码";
CM_ SG_ 2417553023 S2P_Cfg8_SW_Ver_Byte2_63 "CSC软件版本号Byte2对应的ASCII码";
CM_ SG_ 2417553023 S2P_Cfg8_SW_Ver_Byte3_63 "CSC软件版本号Byte3对应的ASCII码";
CM_ SG_ 2417553023 S2P_Cfg8_SW_Ver_Byte4_63 "CSC软件版本号Byte4对应的ASCII码";
CM_ SG_ 2417553023 S2P_Cfg8_SW_Ver_Byte5_63 "CSC软件版本号Byte5对应的ASCII码";
CM_ SG_ 2417553023 S2P_Cfg8_SW_Ver_Byte6_63 "CSC软件版本号Byte6对应的ASCII码";
CM_ SG_ 2417553023 S2P_Cfg8_SW_Ver_Byte7_63 "CSC软件版本号Byte7对应的ASCII码";
CM_ SG_ 2417553023 S2P_Cfg8_SW_Ver_Byte8_63 "CSC软件版本号Byte8对应的ASCII码";
CM_ SG_ 2417618497 S2P_Cfg9_SW_Ver_Byte9_01 "CSC软件版本号Byte9对应的ASCII码";
CM_ SG_ 2417618497 S2P_Cfg9_SW_Ver_Byte10_01 "CSC软件版本号Byte10对应的ASCII码";
CM_ SG_ 2417618497 S2P_Cfg9_SW_Ver_Byte11_01 "CSC软件版本号Byte11对应的ASCII码";
CM_ SG_ 2417618497 S2P_Cfg9_SW_Ver_Byte12_01 "CSC软件版本号Byte12对应的ASCII码";
CM_ SG_ 2417618497 S2P_Cfg9_SW_Ver_Byte13_01 "CSC软件版本号Byte13对应的ASCII码";
CM_ SG_ 2417618497 S2P_Cfg9_SW_Ver_Byte14_01 "CSC软件版本号Byte14对应的ASCII码";
CM_ SG_ 2417618497 S2P_Cfg9_SW_Ver_Byte15_01 "CSC软件版本号Byte15对应的ASCII码";
CM_ SG_ 2417618497 S2P_Cfg9_SW_Ver_Byte16_01 "CSC软件版本号最高字节Byte16对应的ASCII码";
CM_ SG_ 2417618498 S2P_Cfg9_SW_Ver_Byte9_02 "CSC软件版本号Byte9对应的ASCII码";
CM_ SG_ 2417618498 S2P_Cfg9_SW_Ver_Byte10_02 "CSC软件版本号Byte10对应的ASCII码";
CM_ SG_ 2417618498 S2P_Cfg9_SW_Ver_Byte11_02 "CSC软件版本号Byte11对应的ASCII码";
CM_ SG_ 2417618498 S2P_Cfg9_SW_Ver_Byte12_02 "CSC软件版本号Byte12对应的ASCII码";
CM_ SG_ 2417618498 S2P_Cfg9_SW_Ver_Byte13_02 "CSC软件版本号Byte13对应的ASCII码";
CM_ SG_ 2417618498 S2P_Cfg9_SW_Ver_Byte14_02 "CSC软件版本号Byte14对应的ASCII码";
CM_ SG_ 2417618498 S2P_Cfg9_SW_Ver_Byte15_02 "CSC软件版本号Byte15对应的ASCII码";
CM_ SG_ 2417618498 S2P_Cfg9_SW_Ver_Byte16_02 "CSC软件版本号最高字节Byte16对应的ASCII码";
CM_ SG_ 2417618499 S2P_Cfg9_SW_Ver_Byte9_03 "CSC软件版本号Byte9对应的ASCII码";
CM_ SG_ 2417618499 S2P_Cfg9_SW_Ver_Byte10_03 "CSC软件版本号Byte10对应的ASCII码";
CM_ SG_ 2417618499 S2P_Cfg9_SW_Ver_Byte11_03 "CSC软件版本号Byte11对应的ASCII码";
CM_ SG_ 2417618499 S2P_Cfg9_SW_Ver_Byte12_03 "CSC软件版本号Byte12对应的ASCII码";
CM_ SG_ 2417618499 S2P_Cfg9_SW_Ver_Byte13_03 "CSC软件版本号Byte13对应的ASCII码";
CM_ SG_ 2417618499 S2P_Cfg9_SW_Ver_Byte14_03 "CSC软件版本号Byte14对应的ASCII码";
CM_ SG_ 2417618499 S2P_Cfg9_SW_Ver_Byte15_03 "CSC软件版本号Byte15对应的ASCII码";
CM_ SG_ 2417618499 S2P_Cfg9_SW_Ver_Byte16_03 "CSC软件版本号最高字节Byte16对应的ASCII码";
CM_ SG_ 2417618500 S2P_Cfg9_SW_Ver_Byte9_04 "CSC软件版本号Byte9对应的ASCII码";
CM_ SG_ 2417618500 S2P_Cfg9_SW_Ver_Byte10_04 "CSC软件版本号Byte10对应的ASCII码";
CM_ SG_ 2417618500 S2P_Cfg9_SW_Ver_Byte11_04 "CSC软件版本号Byte11对应的ASCII码";
CM_ SG_ 2417618500 S2P_Cfg9_SW_Ver_Byte12_04 "CSC软件版本号Byte12对应的ASCII码";
CM_ SG_ 2417618500 S2P_Cfg9_SW_Ver_Byte13_04 "CSC软件版本号Byte13对应的ASCII码";
CM_ SG_ 2417618500 S2P_Cfg9_SW_Ver_Byte14_04 "CSC软件版本号Byte14对应的ASCII码";
CM_ SG_ 2417618500 S2P_Cfg9_SW_Ver_Byte15_04 "CSC软件版本号Byte15对应的ASCII码";
CM_ SG_ 2417618500 S2P_Cfg9_SW_Ver_Byte16_04 "CSC软件版本号最高字节Byte16对应的ASCII码";
CM_ SG_ 2417618501 S2P_Cfg9_SW_Ver_Byte9_05 "CSC软件版本号Byte9对应的ASCII码";
CM_ SG_ 2417618501 S2P_Cfg9_SW_Ver_Byte10_05 "CSC软件版本号Byte10对应的ASCII码";
CM_ SG_ 2417618501 S2P_Cfg9_SW_Ver_Byte11_05 "CSC软件版本号Byte11对应的ASCII码";
CM_ SG_ 2417618501 S2P_Cfg9_SW_Ver_Byte12_05 "CSC软件版本号Byte12对应的ASCII码";
CM_ SG_ 2417618501 S2P_Cfg9_SW_Ver_Byte13_05 "CSC软件版本号Byte13对应的ASCII码";
CM_ SG_ 2417618501 S2P_Cfg9_SW_Ver_Byte14_05 "CSC软件版本号Byte14对应的ASCII码";
CM_ SG_ 2417618501 S2P_Cfg9_SW_Ver_Byte15_05 "CSC软件版本号Byte15对应的ASCII码";
CM_ SG_ 2417618501 S2P_Cfg9_SW_Ver_Byte16_05 "CSC软件版本号最高字节Byte16对应的ASCII码";
CM_ SG_ 2417618502 S2P_Cfg9_SW_Ver_Byte9_06 "CSC软件版本号Byte9对应的ASCII码";
CM_ SG_ 2417618502 S2P_Cfg9_SW_Ver_Byte10_06 "CSC软件版本号Byte10对应的ASCII码";
CM_ SG_ 2417618502 S2P_Cfg9_SW_Ver_Byte11_06 "CSC软件版本号Byte11对应的ASCII码";
CM_ SG_ 2417618502 S2P_Cfg9_SW_Ver_Byte12_06 "CSC软件版本号Byte12对应的ASCII码";
CM_ SG_ 2417618502 S2P_Cfg9_SW_Ver_Byte13_06 "CSC软件版本号Byte13对应的ASCII码";
CM_ SG_ 2417618502 S2P_Cfg9_SW_Ver_Byte14_06 "CSC软件版本号Byte14对应的ASCII码";
CM_ SG_ 2417618502 S2P_Cfg9_SW_Ver_Byte15_06 "CSC软件版本号Byte15对应的ASCII码";
CM_ SG_ 2417618502 S2P_Cfg9_SW_Ver_Byte16_06 "CSC软件版本号最高字节Byte16对应的ASCII码";
CM_ SG_ 2417618503 S2P_Cfg9_SW_Ver_Byte9_07 "CSC软件版本号Byte9对应的ASCII码";
CM_ SG_ 2417618503 S2P_Cfg9_SW_Ver_Byte10_07 "CSC软件版本号Byte10对应的ASCII码";
CM_ SG_ 2417618503 S2P_Cfg9_SW_Ver_Byte11_07 "CSC软件版本号Byte11对应的ASCII码";
CM_ SG_ 2417618503 S2P_Cfg9_SW_Ver_Byte12_07 "CSC软件版本号Byte12对应的ASCII码";
CM_ SG_ 2417618503 S2P_Cfg9_SW_Ver_Byte13_07 "CSC软件版本号Byte13对应的ASCII码";
CM_ SG_ 2417618503 S2P_Cfg9_SW_Ver_Byte14_07 "CSC软件版本号Byte14对应的ASCII码";
CM_ SG_ 2417618503 S2P_Cfg9_SW_Ver_Byte15_07 "CSC软件版本号Byte15对应的ASCII码";
CM_ SG_ 2417618503 S2P_Cfg9_SW_Ver_Byte16_07 "CSC软件版本号最高字节Byte16对应的ASCII码";
CM_ SG_ 2417618504 S2P_Cfg9_SW_Ver_Byte9_08 "CSC软件版本号Byte9对应的ASCII码";
CM_ SG_ 2417618504 S2P_Cfg9_SW_Ver_Byte10_08 "CSC软件版本号Byte10对应的ASCII码";
CM_ SG_ 2417618504 S2P_Cfg9_SW_Ver_Byte11_08 "CSC软件版本号Byte11对应的ASCII码";
CM_ SG_ 2417618504 S2P_Cfg9_SW_Ver_Byte12_08 "CSC软件版本号Byte12对应的ASCII码";
CM_ SG_ 2417618504 S2P_Cfg9_SW_Ver_Byte13_08 "CSC软件版本号Byte13对应的ASCII码";
CM_ SG_ 2417618504 S2P_Cfg9_SW_Ver_Byte14_08 "CSC软件版本号Byte14对应的ASCII码";
CM_ SG_ 2417618504 S2P_Cfg9_SW_Ver_Byte15_08 "CSC软件版本号Byte15对应的ASCII码";
CM_ SG_ 2417618504 S2P_Cfg9_SW_Ver_Byte16_08 "CSC软件版本号最高字节Byte16对应的ASCII码";
CM_ SG_ 2417618505 S2P_Cfg9_SW_Ver_Byte9_09 "CSC软件版本号Byte9对应的ASCII码";
CM_ SG_ 2417618505 S2P_Cfg9_SW_Ver_Byte10_09 "CSC软件版本号Byte10对应的ASCII码";
CM_ SG_ 2417618505 S2P_Cfg9_SW_Ver_Byte11_09 "CSC软件版本号Byte11对应的ASCII码";
CM_ SG_ 2417618505 S2P_Cfg9_SW_Ver_Byte12_09 "CSC软件版本号Byte12对应的ASCII码";
CM_ SG_ 2417618505 S2P_Cfg9_SW_Ver_Byte13_09 "CSC软件版本号Byte13对应的ASCII码";
CM_ SG_ 2417618505 S2P_Cfg9_SW_Ver_Byte14_09 "CSC软件版本号Byte14对应的ASCII码";
CM_ SG_ 2417618505 S2P_Cfg9_SW_Ver_Byte15_09 "CSC软件版本号Byte15对应的ASCII码";
CM_ SG_ 2417618505 S2P_Cfg9_SW_Ver_Byte16_09 "CSC软件版本号最高字节Byte16对应的ASCII码";
CM_ SG_ 2417618506 S2P_Cfg9_SW_Ver_Byte9_10 "CSC软件版本号Byte9对应的ASCII码";
CM_ SG_ 2417618506 S2P_Cfg9_SW_Ver_Byte10_10 "CSC软件版本号Byte10对应的ASCII码";
CM_ SG_ 2417618506 S2P_Cfg9_SW_Ver_Byte11_10 "CSC软件版本号Byte11对应的ASCII码";
CM_ SG_ 2417618506 S2P_Cfg9_SW_Ver_Byte12_10 "CSC软件版本号Byte12对应的ASCII码";
CM_ SG_ 2417618506 S2P_Cfg9_SW_Ver_Byte13_10 "CSC软件版本号Byte13对应的ASCII码";
CM_ SG_ 2417618506 S2P_Cfg9_SW_Ver_Byte14_10 "CSC软件版本号Byte14对应的ASCII码";
CM_ SG_ 2417618506 S2P_Cfg9_SW_Ver_Byte15_10 "CSC软件版本号Byte15对应的ASCII码";
CM_ SG_ 2417618506 S2P_Cfg9_SW_Ver_Byte16_10 "CSC软件版本号最高字节Byte16对应的ASCII码";
CM_ SG_ 2417618507 S2P_Cfg9_SW_Ver_Byte9_11 "CSC软件版本号Byte9对应的ASCII码";
CM_ SG_ 2417618507 S2P_Cfg9_SW_Ver_Byte10_11 "CSC软件版本号Byte10对应的ASCII码";
CM_ SG_ 2417618507 S2P_Cfg9_SW_Ver_Byte11_11 "CSC软件版本号Byte11对应的ASCII码";
CM_ SG_ 2417618507 S2P_Cfg9_SW_Ver_Byte12_11 "CSC软件版本号Byte12对应的ASCII码";
CM_ SG_ 2417618507 S2P_Cfg9_SW_Ver_Byte13_11 "CSC软件版本号Byte13对应的ASCII码";
CM_ SG_ 2417618507 S2P_Cfg9_SW_Ver_Byte14_11 "CSC软件版本号Byte14对应的ASCII码";
CM_ SG_ 2417618507 S2P_Cfg9_SW_Ver_Byte15_11 "CSC软件版本号Byte15对应的ASCII码";
CM_ SG_ 2417618507 S2P_Cfg9_SW_Ver_Byte16_11 "CSC软件版本号最高字节Byte16对应的ASCII码";
CM_ SG_ 2417618508 S2P_Cfg9_SW_Ver_Byte9_12 "CSC软件版本号Byte9对应的ASCII码";
CM_ SG_ 2417618508 S2P_Cfg9_SW_Ver_Byte10_12 "CSC软件版本号Byte10对应的ASCII码";
CM_ SG_ 2417618508 S2P_Cfg9_SW_Ver_Byte11_12 "CSC软件版本号Byte11对应的ASCII码";
CM_ SG_ 2417618508 S2P_Cfg9_SW_Ver_Byte12_12 "CSC软件版本号Byte12对应的ASCII码";
CM_ SG_ 2417618508 S2P_Cfg9_SW_Ver_Byte13_12 "CSC软件版本号Byte13对应的ASCII码";
CM_ SG_ 2417618508 S2P_Cfg9_SW_Ver_Byte14_12 "CSC软件版本号Byte14对应的ASCII码";
CM_ SG_ 2417618508 S2P_Cfg9_SW_Ver_Byte15_12 "CSC软件版本号Byte15对应的ASCII码";
CM_ SG_ 2417618508 S2P_Cfg9_SW_Ver_Byte16_12 "CSC软件版本号最高字节Byte16对应的ASCII码";
CM_ SG_ 2417618509 S2P_Cfg9_SW_Ver_Byte9_13 "CSC软件版本号Byte9对应的ASCII码";
CM_ SG_ 2417618509 S2P_Cfg9_SW_Ver_Byte10_13 "CSC软件版本号Byte10对应的ASCII码";
CM_ SG_ 2417618509 S2P_Cfg9_SW_Ver_Byte11_13 "CSC软件版本号Byte11对应的ASCII码";
CM_ SG_ 2417618509 S2P_Cfg9_SW_Ver_Byte12_13 "CSC软件版本号Byte12对应的ASCII码";
CM_ SG_ 2417618509 S2P_Cfg9_SW_Ver_Byte13_13 "CSC软件版本号Byte13对应的ASCII码";
CM_ SG_ 2417618509 S2P_Cfg9_SW_Ver_Byte14_13 "CSC软件版本号Byte14对应的ASCII码";
CM_ SG_ 2417618509 S2P_Cfg9_SW_Ver_Byte15_13 "CSC软件版本号Byte15对应的ASCII码";
CM_ SG_ 2417618509 S2P_Cfg9_SW_Ver_Byte16_13 "CSC软件版本号最高字节Byte16对应的ASCII码";
CM_ SG_ 2417618510 S2P_Cfg9_SW_Ver_Byte9_14 "CSC软件版本号Byte9对应的ASCII码";
CM_ SG_ 2417618510 S2P_Cfg9_SW_Ver_Byte10_14 "CSC软件版本号Byte10对应的ASCII码";
CM_ SG_ 2417618510 S2P_Cfg9_SW_Ver_Byte11_14 "CSC软件版本号Byte11对应的ASCII码";
CM_ SG_ 2417618510 S2P_Cfg9_SW_Ver_Byte12_14 "CSC软件版本号Byte12对应的ASCII码";
CM_ SG_ 2417618510 S2P_Cfg9_SW_Ver_Byte13_14 "CSC软件版本号Byte13对应的ASCII码";
CM_ SG_ 2417618510 S2P_Cfg9_SW_Ver_Byte14_14 "CSC软件版本号Byte14对应的ASCII码";
CM_ SG_ 2417618510 S2P_Cfg9_SW_Ver_Byte15_14 "CSC软件版本号Byte15对应的ASCII码";
CM_ SG_ 2417618510 S2P_Cfg9_SW_Ver_Byte16_14 "CSC软件版本号最高字节Byte16对应的ASCII码";
CM_ SG_ 2417618511 S2P_Cfg9_SW_Ver_Byte9_15 "CSC软件版本号Byte9对应的ASCII码";
CM_ SG_ 2417618511 S2P_Cfg9_SW_Ver_Byte10_15 "CSC软件版本号Byte10对应的ASCII码";
CM_ SG_ 2417618511 S2P_Cfg9_SW_Ver_Byte11_15 "CSC软件版本号Byte11对应的ASCII码";
CM_ SG_ 2417618511 S2P_Cfg9_SW_Ver_Byte12_15 "CSC软件版本号Byte12对应的ASCII码";
CM_ SG_ 2417618511 S2P_Cfg9_SW_Ver_Byte13_15 "CSC软件版本号Byte13对应的ASCII码";
CM_ SG_ 2417618511 S2P_Cfg9_SW_Ver_Byte14_15 "CSC软件版本号Byte14对应的ASCII码";
CM_ SG_ 2417618511 S2P_Cfg9_SW_Ver_Byte15_15 "CSC软件版本号Byte15对应的ASCII码";
CM_ SG_ 2417618511 S2P_Cfg9_SW_Ver_Byte16_15 "CSC软件版本号最高字节Byte16对应的ASCII码";
CM_ SG_ 2417618512 S2P_Cfg9_SW_Ver_Byte9_16 "CSC软件版本号Byte9对应的ASCII码";
CM_ SG_ 2417618512 S2P_Cfg9_SW_Ver_Byte10_16 "CSC软件版本号Byte10对应的ASCII码";
CM_ SG_ 2417618512 S2P_Cfg9_SW_Ver_Byte11_16 "CSC软件版本号Byte11对应的ASCII码";
CM_ SG_ 2417618512 S2P_Cfg9_SW_Ver_Byte12_16 "CSC软件版本号Byte12对应的ASCII码";
CM_ SG_ 2417618512 S2P_Cfg9_SW_Ver_Byte13_16 "CSC软件版本号Byte13对应的ASCII码";
CM_ SG_ 2417618512 S2P_Cfg9_SW_Ver_Byte14_16 "CSC软件版本号Byte14对应的ASCII码";
CM_ SG_ 2417618512 S2P_Cfg9_SW_Ver_Byte15_16 "CSC软件版本号Byte15对应的ASCII码";
CM_ SG_ 2417618512 S2P_Cfg9_SW_Ver_Byte16_16 "CSC软件版本号最高字节Byte16对应的ASCII码";
CM_ SG_ 2417618513 S2P_Cfg9_SW_Ver_Byte9_17 "CSC软件版本号Byte9对应的ASCII码";
CM_ SG_ 2417618513 S2P_Cfg9_SW_Ver_Byte10_17 "CSC软件版本号Byte10对应的ASCII码";
CM_ SG_ 2417618513 S2P_Cfg9_SW_Ver_Byte11_17 "CSC软件版本号Byte11对应的ASCII码";
CM_ SG_ 2417618513 S2P_Cfg9_SW_Ver_Byte12_17 "CSC软件版本号Byte12对应的ASCII码";
CM_ SG_ 2417618513 S2P_Cfg9_SW_Ver_Byte13_17 "CSC软件版本号Byte13对应的ASCII码";
CM_ SG_ 2417618513 S2P_Cfg9_SW_Ver_Byte14_17 "CSC软件版本号Byte14对应的ASCII码";
CM_ SG_ 2417618513 S2P_Cfg9_SW_Ver_Byte15_17 "CSC软件版本号Byte15对应的ASCII码";
CM_ SG_ 2417618513 S2P_Cfg9_SW_Ver_Byte16_17 "CSC软件版本号最高字节Byte16对应的ASCII码";
CM_ SG_ 2417618514 S2P_Cfg9_SW_Ver_Byte9_18 "CSC软件版本号Byte9对应的ASCII码";
CM_ SG_ 2417618514 S2P_Cfg9_SW_Ver_Byte10_18 "CSC软件版本号Byte10对应的ASCII码";
CM_ SG_ 2417618514 S2P_Cfg9_SW_Ver_Byte11_18 "CSC软件版本号Byte11对应的ASCII码";
CM_ SG_ 2417618514 S2P_Cfg9_SW_Ver_Byte12_18 "CSC软件版本号Byte12对应的ASCII码";
CM_ SG_ 2417618514 S2P_Cfg9_SW_Ver_Byte13_18 "CSC软件版本号Byte13对应的ASCII码";
CM_ SG_ 2417618514 S2P_Cfg9_SW_Ver_Byte14_18 "CSC软件版本号Byte14对应的ASCII码";
CM_ SG_ 2417618514 S2P_Cfg9_SW_Ver_Byte15_18 "CSC软件版本号Byte15对应的ASCII码";
CM_ SG_ 2417618514 S2P_Cfg9_SW_Ver_Byte16_18 "CSC软件版本号最高字节Byte16对应的ASCII码";
CM_ SG_ 2417618515 S2P_Cfg9_SW_Ver_Byte9_19 "CSC软件版本号Byte9对应的ASCII码";
CM_ SG_ 2417618515 S2P_Cfg9_SW_Ver_Byte10_19 "CSC软件版本号Byte10对应的ASCII码";
CM_ SG_ 2417618515 S2P_Cfg9_SW_Ver_Byte11_19 "CSC软件版本号Byte11对应的ASCII码";
CM_ SG_ 2417618515 S2P_Cfg9_SW_Ver_Byte12_19 "CSC软件版本号Byte12对应的ASCII码";
CM_ SG_ 2417618515 S2P_Cfg9_SW_Ver_Byte13_19 "CSC软件版本号Byte13对应的ASCII码";
CM_ SG_ 2417618515 S2P_Cfg9_SW_Ver_Byte14_19 "CSC软件版本号Byte14对应的ASCII码";
CM_ SG_ 2417618515 S2P_Cfg9_SW_Ver_Byte15_19 "CSC软件版本号Byte15对应的ASCII码";
CM_ SG_ 2417618515 S2P_Cfg9_SW_Ver_Byte16_19 "CSC软件版本号最高字节Byte16对应的ASCII码";
CM_ SG_ 2417618516 S2P_Cfg9_SW_Ver_Byte9_20 "CSC软件版本号Byte9对应的ASCII码";
CM_ SG_ 2417618516 S2P_Cfg9_SW_Ver_Byte10_20 "CSC软件版本号Byte10对应的ASCII码";
CM_ SG_ 2417618516 S2P_Cfg9_SW_Ver_Byte11_20 "CSC软件版本号Byte11对应的ASCII码";
CM_ SG_ 2417618516 S2P_Cfg9_SW_Ver_Byte12_20 "CSC软件版本号Byte12对应的ASCII码";
CM_ SG_ 2417618516 S2P_Cfg9_SW_Ver_Byte13_20 "CSC软件版本号Byte13对应的ASCII码";
CM_ SG_ 2417618516 S2P_Cfg9_SW_Ver_Byte14_20 "CSC软件版本号Byte14对应的ASCII码";
CM_ SG_ 2417618516 S2P_Cfg9_SW_Ver_Byte15_20 "CSC软件版本号Byte15对应的ASCII码";
CM_ SG_ 2417618516 S2P_Cfg9_SW_Ver_Byte16_20 "CSC软件版本号最高字节Byte16对应的ASCII码";
CM_ SG_ 2417618517 S2P_Cfg9_SW_Ver_Byte9_21 "CSC软件版本号Byte9对应的ASCII码";
CM_ SG_ 2417618517 S2P_Cfg9_SW_Ver_Byte10_21 "CSC软件版本号Byte10对应的ASCII码";
CM_ SG_ 2417618517 S2P_Cfg9_SW_Ver_Byte11_21 "CSC软件版本号Byte11对应的ASCII码";
CM_ SG_ 2417618517 S2P_Cfg9_SW_Ver_Byte12_21 "CSC软件版本号Byte12对应的ASCII码";
CM_ SG_ 2417618517 S2P_Cfg9_SW_Ver_Byte13_21 "CSC软件版本号Byte13对应的ASCII码";
CM_ SG_ 2417618517 S2P_Cfg9_SW_Ver_Byte14_21 "CSC软件版本号Byte14对应的ASCII码";
CM_ SG_ 2417618517 S2P_Cfg9_SW_Ver_Byte15_21 "CSC软件版本号Byte15对应的ASCII码";
CM_ SG_ 2417618517 S2P_Cfg9_SW_Ver_Byte16_21 "CSC软件版本号最高字节Byte16对应的ASCII码";
VAL_ 2416373337 S2P_Cfg5_CSCType_25 0 "PBV1.1_52S_16 CSC" 1 "PBV1.1_52S_52_CSC" 2 "PBV1.1_104S_60 CSC" ;
VAL_ 2416373338 S2P_Cfg5_CSCType_26 0 "PBV1.1_52S_16 CSC" 1 "PBV1.1_52S_52_CSC" 2 "PBV1.1_104S_60 CSC" ;
VAL_ 2416373339 S2P_Cfg5_CSCType_27 0 "PBV1.1_52S_16 CSC" 1 "PBV1.1_52S_52_CSC" 2 "PBV1.1_104S_60 CSC" ;
VAL_ 2416373340 S2P_Cfg5_CSCType_28 0 "PBV1.1_52S_16 CSC" 1 "PBV1.1_52S_52_CSC" 2 "PBV1.1_104S_60 CSC" ;
VAL_ 2416373341 S2P_Cfg5_CSCType_29 0 "PBV1.1_52S_16 CSC" 1 "PBV1.1_52S_52_CSC" 2 "PBV1.1_104S_60 CSC" ;
VAL_ 2416373342 S2P_Cfg5_CSCType_30 0 "PBV1.1_52S_16 CSC" 1 "PBV1.1_52S_52_CSC" 2 "PBV1.1_104S_60 CSC" ;
VAL_ 2416373343 S2P_Cfg5_CSCType_31 0 "PBV1.1_52S_16 CSC" 1 "PBV1.1_52S_52_CSC" 2 "PBV1.1_104S_60 CSC" ;
VAL_ 2416373344 S2P_Cfg5_CSCType_32 0 "PBV1.1_52S_16 CSC" 1 "PBV1.1_52S_52_CSC" 2 "PBV1.1_104S_60 CSC" ;
VAL_ 2416373345 S2P_Cfg5_CSCType_33 0 "PBV1.1_52S_16 CSC" 1 "PBV1.1_52S_52_CSC" 2 "PBV1.1_104S_60 CSC" ;
VAL_ 2416373346 S2P_Cfg5_CSCType_34 0 "PBV1.1_52S_16 CSC" 1 "PBV1.1_52S_52_CSC" 2 "PBV1.1_104S_60 CSC" ;
VAL_ 2416373347 S2P_Cfg5_CSCType_35 0 "PBV1.1_52S_16 CSC" 1 "PBV1.1_52S_52_CSC" 2 "PBV1.1_104S_60 CSC" ;
VAL_ 2416373348 S2P_Cfg5_CSCType_36 0 "PBV1.1_52S_16 CSC" 1 "PBV1.1_52S_52_CSC" 2 "PBV1.1_104S_60 CSC" ;
VAL_ 2416373349 S2P_Cfg5_CSCType_37 0 "PBV1.1_52S_16 CSC" 1 "PBV1.1_52S_52_CSC" 2 "PBV1.1_104S_60 CSC" ;
VAL_ 2416373350 S2P_Cfg5_CSCType_38 0 "PBV1.1_52S_16 CSC" 1 "PBV1.1_52S_52_CSC" 2 "PBV1.1_104S_60 CSC" ;
VAL_ 2416373351 S2P_Cfg5_CSCType_39 0 "PBV1.1_52S_16 CSC" 1 "PBV1.1_52S_52_CSC" 2 "PBV1.1_104S_60 CSC" ;
VAL_ 2416373352 S2P_Cfg5_CSCType_40 0 "PBV1.1_52S_16 CSC" 1 "PBV1.1_52S_52_CSC" 2 "PBV1.1_104S_60 CSC" ;
VAL_ 2416373353 S2P_Cfg5_CSCType_41 0 "PBV1.1_52S_16 CSC" 1 "PBV1.1_52S_52_CSC" 2 "PBV1.1_104S_60 CSC" ;
VAL_ 2416373354 S2P_Cfg5_CSCType_42 0 "PBV1.1_52S_16 CSC" 1 "PBV1.1_52S_52_CSC" 2 "PBV1.1_104S_60 CSC" ;
VAL_ 2416373355 S2P_Cfg5_CSCType_43 0 "PBV1.1_52S_16 CSC" 1 "PBV1.1_52S_52_CSC" 2 "PBV1.1_104S_60 CSC" ;
VAL_ 2416373356 S2P_Cfg5_CSCType_44 0 "PBV1.1_52S_16 CSC" 1 "PBV1.1_52S_52_CSC" 2 "PBV1.1_104S_60 CSC" ;
VAL_ 2416373357 S2P_Cfg5_CSCType_45 0 "PBV1.1_52S_16 CSC" 1 "PBV1.1_52S_52_CSC" 2 "PBV1.1_104S_60 CSC" ;
VAL_ 2416373358 S2P_Cfg5_CSCType_46 0 "PBV1.1_52S_16 CSC" 1 "PBV1.1_52S_52_CSC" 2 "PBV1.1_104S_60 CSC" ;
VAL_ 2416373359 S2P_Cfg5_CSCType_47 0 "PBV1.1_52S_16 CSC" 1 "PBV1.1_52S_52_CSC" 2 "PBV1.1_104S_60 CSC" ;
VAL_ 2416373360 S2P_Cfg5_CSCType_48 0 "PBV1.1_52S_16 CSC" 1 "PBV1.1_52S_52_CSC" 2 "PBV1.1_104S_60 CSC" ;
VAL_ 2416373361 S2P_Cfg5_CSCType_49 0 "PBV1.1_52S_16 CSC" 1 "PBV1.1_52S_52_CSC" 2 "PBV1.1_104S_60 CSC" ;
VAL_ 2416373362 S2P_Cfg5_CSCType_50 0 "PBV1.1_52S_16 CSC" 1 "PBV1.1_52S_52_CSC" 2 "PBV1.1_104S_60 CSC" ;
VAL_ 2416373363 S2P_Cfg5_CSCType_51 0 "PBV1.1_52S_16 CSC" 1 "PBV1.1_52S_52_CSC" 2 "PBV1.1_104S_60 CSC" ;
VAL_ 2416373364 S2P_Cfg5_CSCType_52 0 "PBV1.1_52S_16 CSC" 1 "PBV1.1_52S_52_CSC" 2 "PBV1.1_104S_60 CSC" ;
VAL_ 2416373365 S2P_Cfg5_CSCType_53 0 "PBV1.1_52S_16 CSC" 1 "PBV1.1_52S_52_CSC" 2 "PBV1.1_104S_60 CSC" ;
VAL_ 2416373366 S2P_Cfg5_CSCType_54 0 "PBV1.1_52S_16 CSC" 1 "PBV1.1_52S_52_CSC" 2 "PBV1.1_104S_60 CSC" ;
VAL_ 2416373367 S2P_Cfg5_CSCType_55 0 "PBV1.1_52S_16 CSC" 1 "PBV1.1_52S_52_CSC" 2 "PBV1.1_104S_60 CSC" ;
VAL_ 2416373368 S2P_Cfg5_CSCType_56 0 "PBV1.1_52S_16 CSC" 1 "PBV1.1_52S_52_CSC" 2 "PBV1.1_104S_60 CSC" ;
VAL_ 2416373369 S2P_Cfg5_CSCType_57 0 "PBV1.1_52S_16 CSC" 1 "PBV1.1_52S_52_CSC" 2 "PBV1.1_104S_60 CSC" ;
VAL_ 2416373370 S2P_Cfg5_CSCType_58 0 "PBV1.1_52S_16 CSC" 1 "PBV1.1_52S_52_CSC" 2 "PBV1.1_104S_60 CSC" ;
VAL_ 2416373371 S2P_Cfg5_CSCType_59 0 "PBV1.1_52S_16 CSC" 1 "PBV1.1_52S_52_CSC" 2 "PBV1.1_104S_60 CSC" ;
VAL_ 2416373372 S2P_Cfg5_CSCType_60 0 "PBV1.1_52S_16 CSC" 1 "PBV1.1_52S_52_CSC" 2 "PBV1.1_104S_60 CSC" ;
VAL_ 2416373373 S2P_Cfg5_CSCType_61 0 "PBV1.1_52S_16 CSC" 1 "PBV1.1_52S_52_CSC" 2 "PBV1.1_104S_60 CSC" ;
VAL_ 2416373374 S2P_Cfg5_CSCType_62 0 "PBV1.1_52S_16 CSC" 1 "PBV1.1_52S_52_CSC" 2 "PBV1.1_104S_60 CSC" ;
VAL_ 2416373375 S2P_Cfg5_CSCType_63 0 "PBV1.1_52S_16 CSC" 1 "PBV1.1_52S_52_CSC" 2 "PBV1.1_104S_60 CSC" ;
VERSION ""

NS_ :

BS_:

BU_: MBMU PC SBMU IMM ETH DCDC LEMS

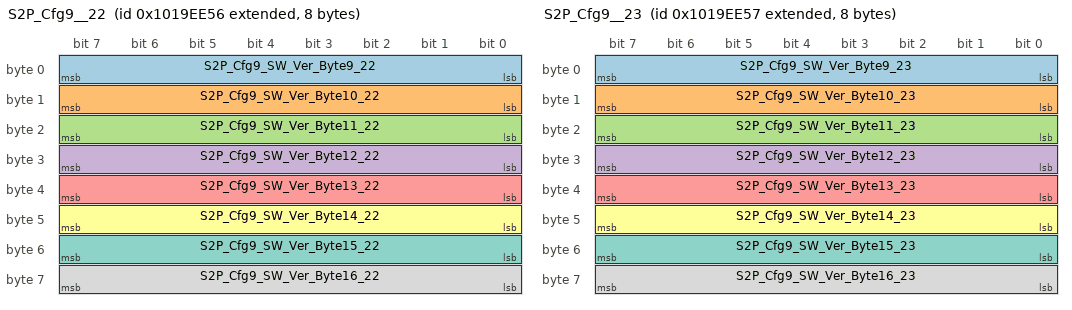
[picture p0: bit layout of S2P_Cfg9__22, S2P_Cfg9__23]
BO_ 2417618518 S2P_Cfg9__22: 8 SBMU
 SG_ S2P_Cfg9_SW_Ver_Byte9_22 : 0|8@1+ (1,0) [0|255] ""  PC
 SG_ S2P_Cfg9_SW_Ver_Byte10_22 : 8|8@1+ (1,0) [0|255] ""  PC
 SG_ S2P_Cfg9_SW_Ver_Byte11_22 : 16|8@1+ (1,0) [0|255] ""  PC
 SG_ S2P_Cfg9_SW_Ver_Byte12_22 : 24|8@1+ (1,0) [0|255] ""  PC
 SG_ S2P_Cfg9_SW_Ver_Byte13_22 : 32|8@1+ (1,0) [0|255] ""  PC
 SG_ S2P_Cfg9_SW_Ver_Byte14_22 : 40|8@1+ (1,0) [0|255] ""  PC
 SG_ S2P_Cfg9_SW_Ver_Byte15_22 : 48|8@1+ (1,0) [0|255] ""  PC
 SG_ S2P_Cfg9_SW_Ver_Byte16_22 : 56|8@1+ (1,0) [0|255] ""  PC

BO_ 2417618519 S2P_Cfg9__23: 8 SBMU
 SG_ S2P_Cfg9_SW_Ver_Byte9_23 : 0|8@1+ (1,0) [0|255] ""  PC
 SG_ S2P_Cfg9_SW_Ver_Byte10_23 : 8|8@1+ (1,0) [0|255] ""  PC
 SG_ S2P_Cfg9_SW_Ver_Byte11_23 : 16|8@1+ (1,0) [0|255] ""  PC
 SG_ S2P_Cfg9_SW_Ver_Byte12_23 : 24|8@1+ (1,0) [0|255] ""  PC
 SG_ S2P_Cfg9_SW_Ver_Byte13_23 : 32|8@1+ (1,0) [0|255] ""  PC
 SG_ S2P_Cfg9_SW_Ver_Byte14_23 : 40|8@1+ (1,0) [0|255] ""  PC
 SG_ S2P_Cfg9_SW_Ver_Byte15_23 : 48|8@1+ (1,0) [0|255] ""  PC
 SG_ S2P_Cfg9_SW_Ver_Byte16_23 : 56|8@1+ (1,0) [0|255] ""  PC

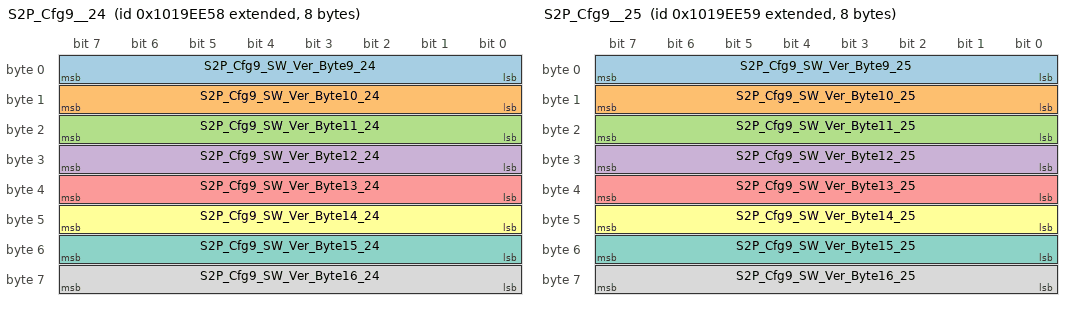
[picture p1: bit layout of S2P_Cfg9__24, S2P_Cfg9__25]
BO_ 2417618520 S2P_Cfg9__24: 8 SBMU
 SG_ S2P_Cfg9_SW_Ver_Byte9_24 : 0|8@1+ (1,0) [0|255] ""  PC
 SG_ S2P_Cfg9_SW_Ver_Byte10_24 : 8|8@1+ (1,0) [0|255] ""  PC
 SG_ S2P_Cfg9_SW_Ver_Byte11_24 : 16|8@1+ (1,0) [0|255] ""  PC
 SG_ S2P_Cfg9_SW_Ver_Byte12_24 : 24|8@1+ (1,0) [0|255] ""  PC
 SG_ S2P_Cfg9_SW_Ver_Byte13_24 : 32|8@1+ (1,0) [0|255] ""  PC
 SG_ S2P_Cfg9_SW_Ver_Byte14_24 : 40|8@1+ (1,0) [0|255] ""  PC
 SG_ S2P_Cfg9_SW_Ver_Byte15_24 : 48|8@1+ (1,0) [0|255] ""  PC
 SG_ S2P_Cfg9_SW_Ver_Byte16_24 : 56|8@1+ (1,0) [0|255] ""  PC

BO_ 2417618521 S2P_Cfg9__25: 8 SBMU
 SG_ S2P_Cfg9_SW_Ver_Byte9_25 : 0|8@1+ (1,0) [0|255] ""  PC
 SG_ S2P_Cfg9_SW_Ver_Byte10_25 : 8|8@1+ (1,0) [0|255] ""  PC
 SG_ S2P_Cfg9_SW_Ver_Byte11_25 : 16|8@1+ (1,0) [0|255] ""  PC
 SG_ S2P_Cfg9_SW_Ver_Byte12_25 : 24|8@1+ (1,0) [0|255] ""  PC
 SG_ S2P_Cfg9_SW_Ver_Byte13_25 : 32|8@1+ (1,0) [0|255] ""  PC
 SG_ S2P_Cfg9_SW_Ver_Byte14_25 : 40|8@1+ (1,0) [0|255] ""  PC
 SG_ S2P_Cfg9_SW_Ver_Byte15_25 : 48|8@1+ (1,0) [0|255] ""  PC
 SG_ S2P_Cfg9_SW_Ver_Byte16_25 : 56|8@1+ (1,0) [0|255] ""  PC

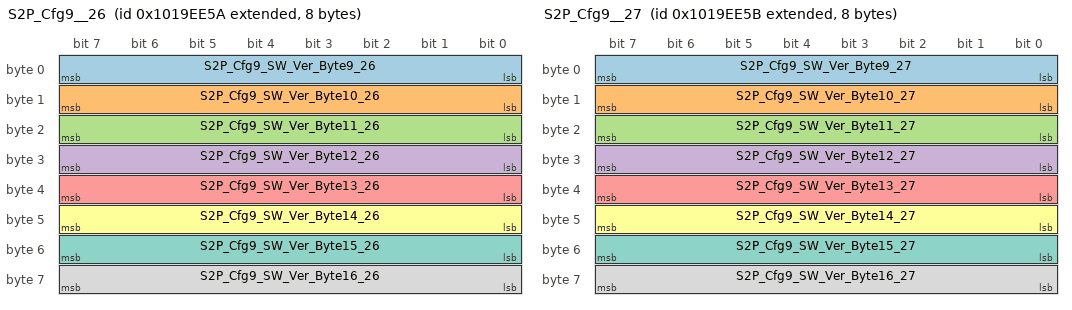
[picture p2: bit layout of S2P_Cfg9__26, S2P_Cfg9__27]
BO_ 2417618522 S2P_Cfg9__26: 8 SBMU
 SG_ S2P_Cfg9_SW_Ver_Byte9_26 : 0|8@1+ (1,0) [0|255] ""  PC
 SG_ S2P_Cfg9_SW_Ver_Byte10_26 : 8|8@1+ (1,0) [0|255] ""  PC
 SG_ S2P_Cfg9_SW_Ver_Byte11_26 : 16|8@1+ (1,0) [0|255] ""  PC
 SG_ S2P_Cfg9_SW_Ver_Byte12_26 : 24|8@1+ (1,0) [0|255] ""  PC
 SG_ S2P_Cfg9_SW_Ver_Byte13_26 : 32|8@1+ (1,0) [0|255] ""  PC
 SG_ S2P_Cfg9_SW_Ver_Byte14_26 : 40|8@1+ (1,0) [0|255] ""  PC
 SG_ S2P_Cfg9_SW_Ver_Byte15_26 : 48|8@1+ (1,0) [0|255] ""  PC
 SG_ S2P_Cfg9_SW_Ver_Byte16_26 : 56|8@1+ (1,0) [0|255] ""  PC

BO_ 2417618523 S2P_Cfg9__27: 8 SBMU
 SG_ S2P_Cfg9_SW_Ver_Byte9_27 : 0|8@1+ (1,0) [0|255] ""  PC
 SG_ S2P_Cfg9_SW_Ver_Byte10_27 : 8|8@1+ (1,0) [0|255] ""  PC
 SG_ S2P_Cfg9_SW_Ver_Byte11_27 : 16|8@1+ (1,0) [0|255] ""  PC
 SG_ S2P_Cfg9_SW_Ver_Byte12_27 : 24|8@1+ (1,0) [0|255] ""  PC
 SG_ S2P_Cfg9_SW_Ver_Byte13_27 : 32|8@1+ (1,0) [0|255] ""  PC
 SG_ S2P_Cfg9_SW_Ver_Byte14_27 : 40|8@1+ (1,0) [0|255] ""  PC
 SG_ S2P_Cfg9_SW_Ver_Byte15_27 : 48|8@1+ (1,0) [0|255] ""  PC
 SG_ S2P_Cfg9_SW_Ver_Byte16_27 : 56|8@1+ (1,0) [0|255] ""  PC

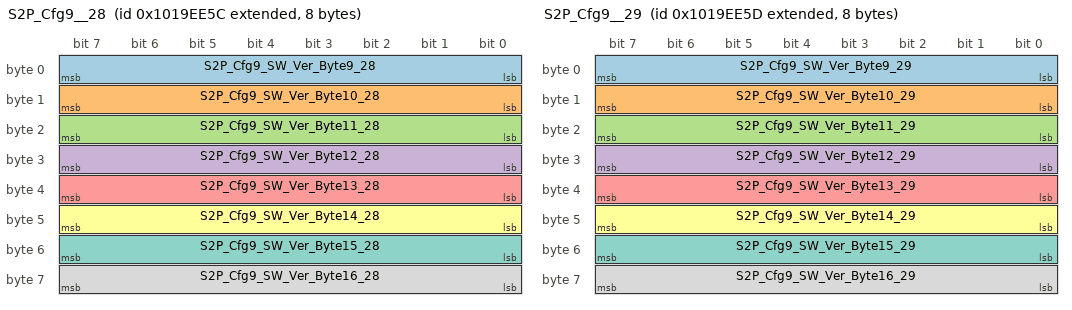
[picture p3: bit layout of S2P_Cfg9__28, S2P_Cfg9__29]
BO_ 2417618524 S2P_Cfg9__28: 8 SBMU
 SG_ S2P_Cfg9_SW_Ver_Byte9_28 : 0|8@1+ (1,0) [0|255] ""  PC
 SG_ S2P_Cfg9_SW_Ver_Byte10_28 : 8|8@1+ (1,0) [0|255] ""  PC
 SG_ S2P_Cfg9_SW_Ver_Byte11_28 : 16|8@1+ (1,0) [0|255] ""  PC
 SG_ S2P_Cfg9_SW_Ver_Byte12_28 : 24|8@1+ (1,0) [0|255] ""  PC
 SG_ S2P_Cfg9_SW_Ver_Byte13_28 : 32|8@1+ (1,0) [0|255] ""  PC
 SG_ S2P_Cfg9_SW_Ver_Byte14_28 : 40|8@1+ (1,0) [0|255] ""  PC
 SG_ S2P_Cfg9_SW_Ver_Byte15_28 : 48|8@1+ (1,0) [0|255] ""  PC
 SG_ S2P_Cfg9_SW_Ver_Byte16_28 : 56|8@1+ (1,0) [0|255] ""  PC

BO_ 2417618525 S2P_Cfg9__29: 8 SBMU
 SG_ S2P_Cfg9_SW_Ver_Byte9_29 : 0|8@1+ (1,0) [0|255] ""  PC
 SG_ S2P_Cfg9_SW_Ver_Byte10_29 : 8|8@1+ (1,0) [0|255] ""  PC
 SG_ S2P_Cfg9_SW_Ver_Byte11_29 : 16|8@1+ (1,0) [0|255] ""  PC
 SG_ S2P_Cfg9_SW_Ver_Byte12_29 : 24|8@1+ (1,0) [0|255] ""  PC
 SG_ S2P_Cfg9_SW_Ver_Byte13_29 : 32|8@1+ (1,0) [0|255] ""  PC
 SG_ S2P_Cfg9_SW_Ver_Byte14_29 : 40|8@1+ (1,0) [0|255] ""  PC
 SG_ S2P_Cfg9_SW_Ver_Byte15_29 : 48|8@1+ (1,0) [0|255] ""  PC
 SG_ S2P_Cfg9_SW_Ver_Byte16_29 : 56|8@1+ (1,0) [0|255] ""  PC

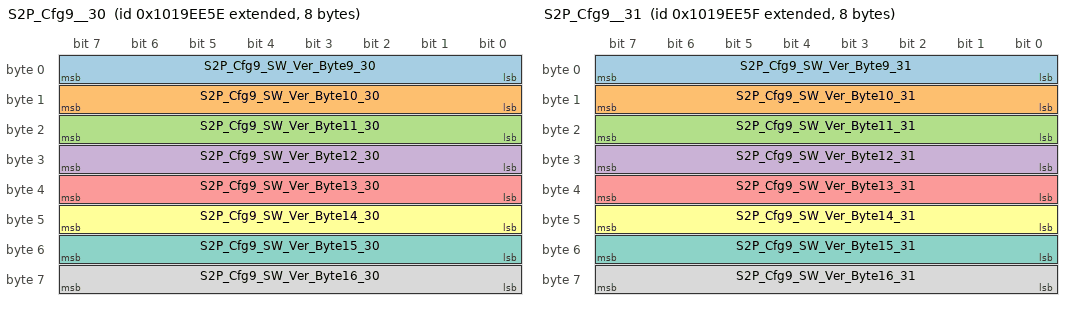
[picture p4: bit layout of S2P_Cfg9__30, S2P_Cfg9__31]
BO_ 2417618526 S2P_Cfg9__30: 8 SBMU
 SG_ S2P_Cfg9_SW_Ver_Byte9_30 : 0|8@1+ (1,0) [0|255] ""  PC
 SG_ S2P_Cfg9_SW_Ver_Byte10_30 : 8|8@1+ (1,0) [0|255] ""  PC
 SG_ S2P_Cfg9_SW_Ver_Byte11_30 : 16|8@1+ (1,0) [0|255] ""  PC
 SG_ S2P_Cfg9_SW_Ver_Byte12_30 : 24|8@1+ (1,0) [0|255] ""  PC
 SG_ S2P_Cfg9_SW_Ver_Byte13_30 : 32|8@1+ (1,0) [0|255] ""  PC
 SG_ S2P_Cfg9_SW_Ver_Byte14_30 : 40|8@1+ (1,0) [0|255] ""  PC
 SG_ S2P_Cfg9_SW_Ver_Byte15_30 : 48|8@1+ (1,0) [0|255] ""  PC
 SG_ S2P_Cfg9_SW_Ver_Byte16_30 : 56|8@1+ (1,0) [0|255] ""  PC

BO_ 2417618527 S2P_Cfg9__31: 8 SBMU
 SG_ S2P_Cfg9_SW_Ver_Byte9_31 : 0|8@1+ (1,0) [0|255] ""  PC
 SG_ S2P_Cfg9_SW_Ver_Byte10_31 : 8|8@1+ (1,0) [0|255] ""  PC
 SG_ S2P_Cfg9_SW_Ver_Byte11_31 : 16|8@1+ (1,0) [0|255] ""  PC
 SG_ S2P_Cfg9_SW_Ver_Byte12_31 : 24|8@1+ (1,0) [0|255] ""  PC
 SG_ S2P_Cfg9_SW_Ver_Byte13_31 : 32|8@1+ (1,0) [0|255] ""  PC
 SG_ S2P_Cfg9_SW_Ver_Byte14_31 : 40|8@1+ (1,0) [0|255] ""  PC
 SG_ S2P_Cfg9_SW_Ver_Byte15_31 : 48|8@1+ (1,0) [0|255] ""  PC
 SG_ S2P_Cfg9_SW_Ver_Byte16_31 : 56|8@1+ (1,0) [0|255] ""  PC

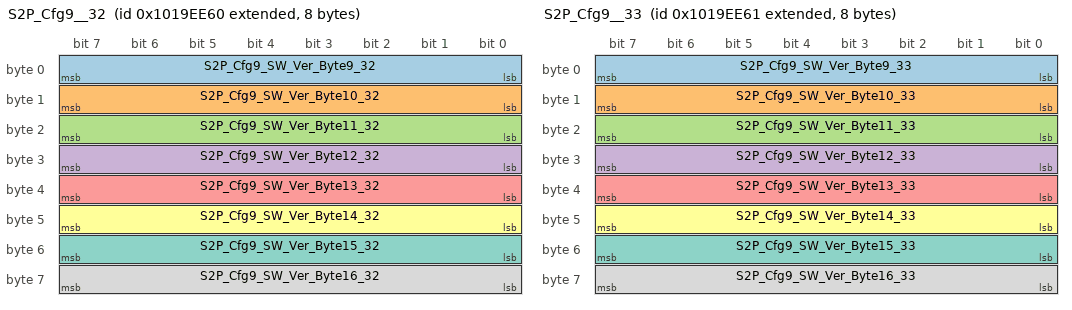
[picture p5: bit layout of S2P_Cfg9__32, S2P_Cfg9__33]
BO_ 2417618528 S2P_Cfg9__32: 8 SBMU
 SG_ S2P_Cfg9_SW_Ver_Byte9_32 : 0|8@1+ (1,0) [0|255] ""  PC
 SG_ S2P_Cfg9_SW_Ver_Byte10_32 : 8|8@1+ (1,0) [0|255] ""  PC
 SG_ S2P_Cfg9_SW_Ver_Byte11_32 : 16|8@1+ (1,0) [0|255] ""  PC
 SG_ S2P_Cfg9_SW_Ver_Byte12_32 : 24|8@1+ (1,0) [0|255] ""  PC
 SG_ S2P_Cfg9_SW_Ver_Byte13_32 : 32|8@1+ (1,0) [0|255] ""  PC
 SG_ S2P_Cfg9_SW_Ver_Byte14_32 : 40|8@1+ (1,0) [0|255] ""  PC
 SG_ S2P_Cfg9_SW_Ver_Byte15_32 : 48|8@1+ (1,0) [0|255] ""  PC
 SG_ S2P_Cfg9_SW_Ver_Byte16_32 : 56|8@1+ (1,0) [0|255] ""  PC

BO_ 2417618529 S2P_Cfg9__33: 8 SBMU
 SG_ S2P_Cfg9_SW_Ver_Byte9_33 : 0|8@1+ (1,0) [0|255] ""  PC
 SG_ S2P_Cfg9_SW_Ver_Byte10_33 : 8|8@1+ (1,0) [0|255] ""  PC
 SG_ S2P_Cfg9_SW_Ver_Byte11_33 : 16|8@1+ (1,0) [0|255] ""  PC
 SG_ S2P_Cfg9_SW_Ver_Byte12_33 : 24|8@1+ (1,0) [0|255] ""  PC
 SG_ S2P_Cfg9_SW_Ver_Byte13_33 : 32|8@1+ (1,0) [0|255] ""  PC
 SG_ S2P_Cfg9_SW_Ver_Byte14_33 : 40|8@1+ (1,0) [0|255] ""  PC
 SG_ S2P_Cfg9_SW_Ver_Byte15_33 : 48|8@1+ (1,0) [0|255] ""  PC
 SG_ S2P_Cfg9_SW_Ver_Byte16_33 : 56|8@1+ (1,0) [0|255] ""  PC

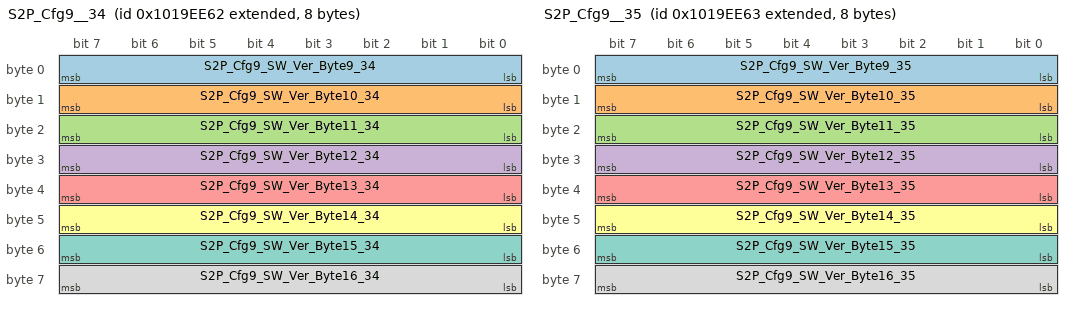
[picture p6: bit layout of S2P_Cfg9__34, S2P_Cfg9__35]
BO_ 2417618530 S2P_Cfg9__34: 8 SBMU
 SG_ S2P_Cfg9_SW_Ver_Byte9_34 : 0|8@1+ (1,0) [0|255] ""  PC
 SG_ S2P_Cfg9_SW_Ver_Byte10_34 : 8|8@1+ (1,0) [0|255] ""  PC
 SG_ S2P_Cfg9_SW_Ver_Byte11_34 : 16|8@1+ (1,0) [0|255] ""  PC
 SG_ S2P_Cfg9_SW_Ver_Byte12_34 : 24|8@1+ (1,0) [0|255] ""  PC
 SG_ S2P_Cfg9_SW_Ver_Byte13_34 : 32|8@1+ (1,0) [0|255] ""  PC
 SG_ S2P_Cfg9_SW_Ver_Byte14_34 : 40|8@1+ (1,0) [0|255] ""  PC
 SG_ S2P_Cfg9_SW_Ver_Byte15_34 : 48|8@1+ (1,0) [0|255] ""  PC
 SG_ S2P_Cfg9_SW_Ver_Byte16_34 : 56|8@1+ (1,0) [0|255] ""  PC

BO_ 2417618531 S2P_Cfg9__35: 8 SBMU
 SG_ S2P_Cfg9_SW_Ver_Byte9_35 : 0|8@1+ (1,0) [0|255] ""  PC
 SG_ S2P_Cfg9_SW_Ver_Byte10_35 : 8|8@1+ (1,0) [0|255] ""  PC
 SG_ S2P_Cfg9_SW_Ver_Byte11_35 : 16|8@1+ (1,0) [0|255] ""  PC
 SG_ S2P_Cfg9_SW_Ver_Byte12_35 : 24|8@1+ (1,0) [0|255] ""  PC
 SG_ S2P_Cfg9_SW_Ver_Byte13_35 : 32|8@1+ (1,0) [0|255] ""  PC
 SG_ S2P_Cfg9_SW_Ver_Byte14_35 : 40|8@1+ (1,0) [0|255] ""  PC
 SG_ S2P_Cfg9_SW_Ver_Byte15_35 : 48|8@1+ (1,0) [0|255] ""  PC
 SG_ S2P_Cfg9_SW_Ver_Byte16_35 : 56|8@1+ (1,0) [0|255] ""  PC

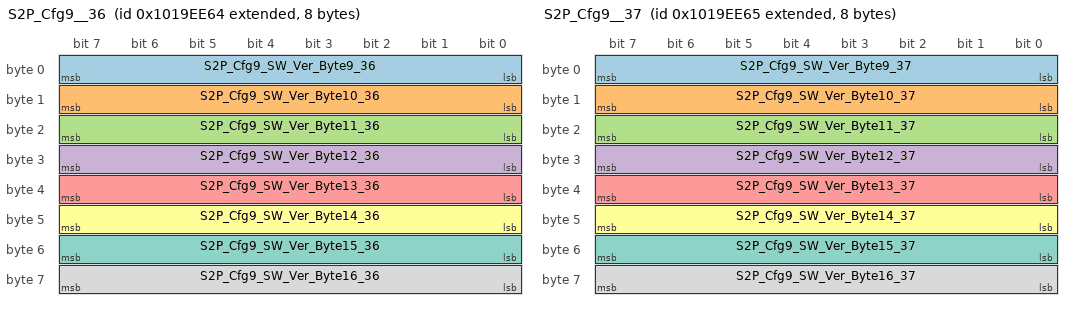
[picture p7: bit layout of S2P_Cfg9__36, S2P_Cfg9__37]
BO_ 2417618532 S2P_Cfg9__36: 8 SBMU
 SG_ S2P_Cfg9_SW_Ver_Byte9_36 : 0|8@1+ (1,0) [0|255] ""  PC
 SG_ S2P_Cfg9_SW_Ver_Byte10_36 : 8|8@1+ (1,0) [0|255] ""  PC
 SG_ S2P_Cfg9_SW_Ver_Byte11_36 : 16|8@1+ (1,0) [0|255] ""  PC
 SG_ S2P_Cfg9_SW_Ver_Byte12_36 : 24|8@1+ (1,0) [0|255] ""  PC
 SG_ S2P_Cfg9_SW_Ver_Byte13_36 : 32|8@1+ (1,0) [0|255] ""  PC
 SG_ S2P_Cfg9_SW_Ver_Byte14_36 : 40|8@1+ (1,0) [0|255] ""  PC
 SG_ S2P_Cfg9_SW_Ver_Byte15_36 : 48|8@1+ (1,0) [0|255] ""  PC
 SG_ S2P_Cfg9_SW_Ver_Byte16_36 : 56|8@1+ (1,0) [0|255] ""  PC

BO_ 2417618533 S2P_Cfg9__37: 8 SBMU
 SG_ S2P_Cfg9_SW_Ver_Byte9_37 : 0|8@1+ (1,0) [0|255] ""  PC
 SG_ S2P_Cfg9_SW_Ver_Byte10_37 : 8|8@1+ (1,0) [0|255] ""  PC
 SG_ S2P_Cfg9_SW_Ver_Byte11_37 : 16|8@1+ (1,0) [0|255] ""  PC
 SG_ S2P_Cfg9_SW_Ver_Byte12_37 : 24|8@1+ (1,0) [0|255] ""  PC
 SG_ S2P_Cfg9_SW_Ver_Byte13_37 : 32|8@1+ (1,0) [0|255] ""  PC
 SG_ S2P_Cfg9_SW_Ver_Byte14_37 : 40|8@1+ (1,0) [0|255] ""  PC
 SG_ S2P_Cfg9_SW_Ver_Byte15_37 : 48|8@1+ (1,0) [0|255] ""  PC
 SG_ S2P_Cfg9_SW_Ver_Byte16_37 : 56|8@1+ (1,0) [0|255] ""  PC

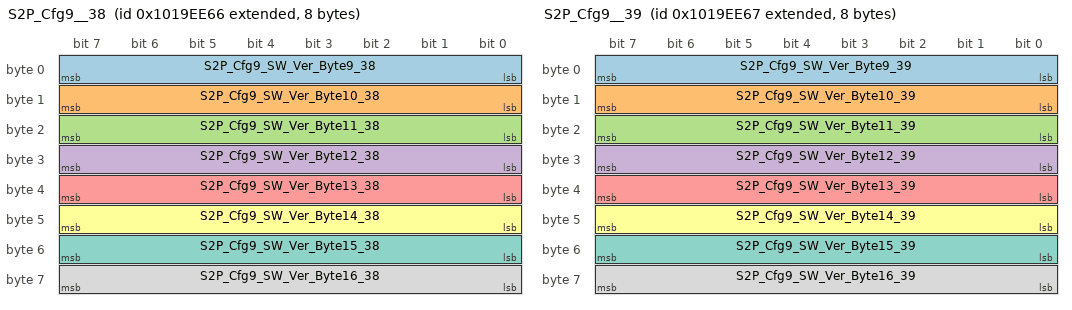
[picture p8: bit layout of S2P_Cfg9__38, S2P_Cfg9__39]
BO_ 2417618534 S2P_Cfg9__38: 8 SBMU
 SG_ S2P_Cfg9_SW_Ver_Byte9_38 : 0|8@1+ (1,0) [0|255] ""  PC
 SG_ S2P_Cfg9_SW_Ver_Byte10_38 : 8|8@1+ (1,0) [0|255] ""  PC
 SG_ S2P_Cfg9_SW_Ver_Byte11_38 : 16|8@1+ (1,0) [0|255] ""  PC
 SG_ S2P_Cfg9_SW_Ver_Byte12_38 : 24|8@1+ (1,0) [0|255] ""  PC
 SG_ S2P_Cfg9_SW_Ver_Byte13_38 : 32|8@1+ (1,0) [0|255] ""  PC
 SG_ S2P_Cfg9_SW_Ver_Byte14_38 : 40|8@1+ (1,0) [0|255] ""  PC
 SG_ S2P_Cfg9_SW_Ver_Byte15_38 : 48|8@1+ (1,0) [0|255] ""  PC
 SG_ S2P_Cfg9_SW_Ver_Byte16_38 : 56|8@1+ (1,0) [0|255] ""  PC

BO_ 2417618535 S2P_Cfg9__39: 8 SBMU
 SG_ S2P_Cfg9_SW_Ver_Byte9_39 : 0|8@1+ (1,0) [0|255] ""  PC
 SG_ S2P_Cfg9_SW_Ver_Byte10_39 : 8|8@1+ (1,0) [0|255] ""  PC
 SG_ S2P_Cfg9_SW_Ver_Byte11_39 : 16|8@1+ (1,0) [0|255] ""  PC
 SG_ S2P_Cfg9_SW_Ver_Byte12_39 : 24|8@1+ (1,0) [0|255] ""  PC
 SG_ S2P_Cfg9_SW_Ver_Byte13_39 : 32|8@1+ (1,0) [0|255] ""  PC
 SG_ S2P_Cfg9_SW_Ver_Byte14_39 : 40|8@1+ (1,0) [0|255] ""  PC
 SG_ S2P_Cfg9_SW_Ver_Byte15_39 : 48|8@1+ (1,0) [0|255] ""  PC
 SG_ S2P_Cfg9_SW_Ver_Byte16_39 : 56|8@1+ (1,0) [0|255] ""  PC

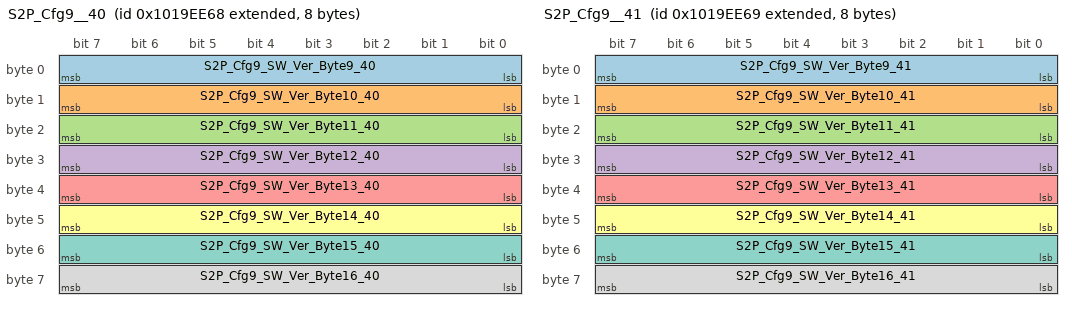
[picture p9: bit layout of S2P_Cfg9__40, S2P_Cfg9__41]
BO_ 2417618536 S2P_Cfg9__40: 8 SBMU
 SG_ S2P_Cfg9_SW_Ver_Byte9_40 : 0|8@1+ (1,0) [0|255] ""  PC
 SG_ S2P_Cfg9_SW_Ver_Byte10_40 : 8|8@1+ (1,0) [0|255] ""  PC
 SG_ S2P_Cfg9_SW_Ver_Byte11_40 : 16|8@1+ (1,0) [0|255] ""  PC
 SG_ S2P_Cfg9_SW_Ver_Byte12_40 : 24|8@1+ (1,0) [0|255] ""  PC
 SG_ S2P_Cfg9_SW_Ver_Byte13_40 : 32|8@1+ (1,0) [0|255] ""  PC
 SG_ S2P_Cfg9_SW_Ver_Byte14_40 : 40|8@1+ (1,0) [0|255] ""  PC
 SG_ S2P_Cfg9_SW_Ver_Byte15_40 : 48|8@1+ (1,0) [0|255] ""  PC
 SG_ S2P_Cfg9_SW_Ver_Byte16_40 : 56|8@1+ (1,0) [0|255] ""  PC

BO_ 2417618537 S2P_Cfg9__41: 8 SBMU
 SG_ S2P_Cfg9_SW_Ver_Byte9_41 : 0|8@1+ (1,0) [0|255] ""  PC
 SG_ S2P_Cfg9_SW_Ver_Byte10_41 : 8|8@1+ (1,0) [0|255] ""  PC
 SG_ S2P_Cfg9_SW_Ver_Byte11_41 : 16|8@1+ (1,0) [0|255] ""  PC
 SG_ S2P_Cfg9_SW_Ver_Byte12_41 : 24|8@1+ (1,0) [0|255] ""  PC
 SG_ S2P_Cfg9_SW_Ver_Byte13_41 : 32|8@1+ (1,0) [0|255] ""  PC
 SG_ S2P_Cfg9_SW_Ver_Byte14_41 : 40|8@1+ (1,0) [0|255] ""  PC
 SG_ S2P_Cfg9_SW_Ver_Byte15_41 : 48|8@1+ (1,0) [0|255] ""  PC
 SG_ S2P_Cfg9_SW_Ver_Byte16_41 : 56|8@1+ (1,0) [0|255] ""  PC

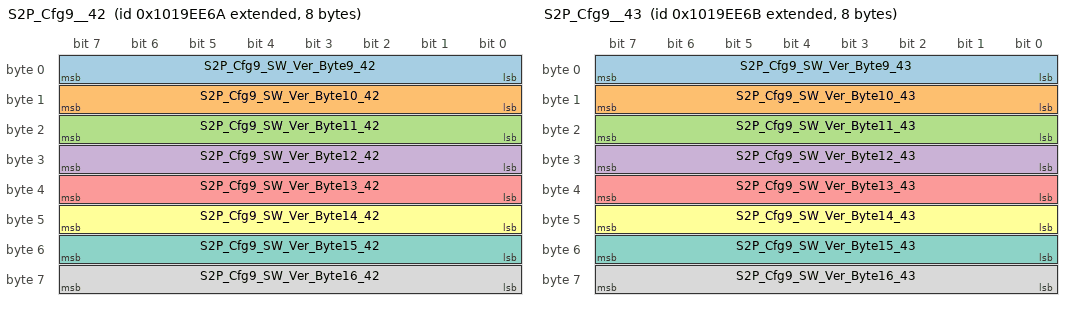
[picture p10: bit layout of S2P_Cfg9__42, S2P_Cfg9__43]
BO_ 2417618538 S2P_Cfg9__42: 8 SBMU
 SG_ S2P_Cfg9_SW_Ver_Byte9_42 : 0|8@1+ (1,0) [0|255] ""  PC
 SG_ S2P_Cfg9_SW_Ver_Byte10_42 : 8|8@1+ (1,0) [0|255] ""  PC
 SG_ S2P_Cfg9_SW_Ver_Byte11_42 : 16|8@1+ (1,0) [0|255] ""  PC
 SG_ S2P_Cfg9_SW_Ver_Byte12_42 : 24|8@1+ (1,0) [0|255] ""  PC
 SG_ S2P_Cfg9_SW_Ver_Byte13_42 : 32|8@1+ (1,0) [0|255] ""  PC
 SG_ S2P_Cfg9_SW_Ver_Byte14_42 : 40|8@1+ (1,0) [0|255] ""  PC
 SG_ S2P_Cfg9_SW_Ver_Byte15_42 : 48|8@1+ (1,0) [0|255] ""  PC
 SG_ S2P_Cfg9_SW_Ver_Byte16_42 : 56|8@1+ (1,0) [0|255] ""  PC

BO_ 2417618539 S2P_Cfg9__43: 8 SBMU
 SG_ S2P_Cfg9_SW_Ver_Byte9_43 : 0|8@1+ (1,0) [0|255] ""  PC
 SG_ S2P_Cfg9_SW_Ver_Byte10_43 : 8|8@1+ (1,0) [0|255] ""  PC
 SG_ S2P_Cfg9_SW_Ver_Byte11_43 : 16|8@1+ (1,0) [0|255] ""  PC
 SG_ S2P_Cfg9_SW_Ver_Byte12_43 : 24|8@1+ (1,0) [0|255] ""  PC
 SG_ S2P_Cfg9_SW_Ver_Byte13_43 : 32|8@1+ (1,0) [0|255] ""  PC
 SG_ S2P_Cfg9_SW_Ver_Byte14_43 : 40|8@1+ (1,0) [0|255] ""  PC
 SG_ S2P_Cfg9_SW_Ver_Byte15_43 : 48|8@1+ (1,0) [0|255] ""  PC
 SG_ S2P_Cfg9_SW_Ver_Byte16_43 : 56|8@1+ (1,0) [0|255] ""  PC

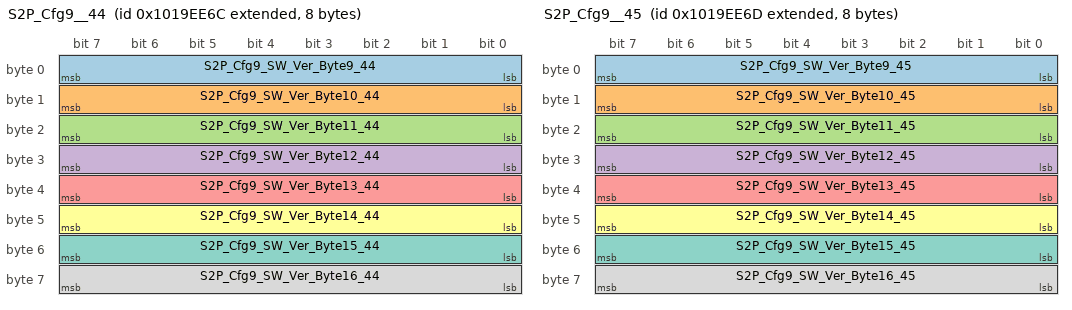
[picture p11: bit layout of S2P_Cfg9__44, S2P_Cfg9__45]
BO_ 2417618540 S2P_Cfg9__44: 8 SBMU
 SG_ S2P_Cfg9_SW_Ver_Byte9_44 : 0|8@1+ (1,0) [0|255] ""  PC
 SG_ S2P_Cfg9_SW_Ver_Byte10_44 : 8|8@1+ (1,0) [0|255] ""  PC
 SG_ S2P_Cfg9_SW_Ver_Byte11_44 : 16|8@1+ (1,0) [0|255] ""  PC
 SG_ S2P_Cfg9_SW_Ver_Byte12_44 : 24|8@1+ (1,0) [0|255] ""  PC
 SG_ S2P_Cfg9_SW_Ver_Byte13_44 : 32|8@1+ (1,0) [0|255] ""  PC
 SG_ S2P_Cfg9_SW_Ver_Byte14_44 : 40|8@1+ (1,0) [0|255] ""  PC
 SG_ S2P_Cfg9_SW_Ver_Byte15_44 : 48|8@1+ (1,0) [0|255] ""  PC
 SG_ S2P_Cfg9_SW_Ver_Byte16_44 : 56|8@1+ (1,0) [0|255] ""  PC

BO_ 2417618541 S2P_Cfg9__45: 8 SBMU
 SG_ S2P_Cfg9_SW_Ver_Byte9_45 : 0|8@1+ (1,0) [0|255] ""  PC
 SG_ S2P_Cfg9_SW_Ver_Byte10_45 : 8|8@1+ (1,0) [0|255] ""  PC
 SG_ S2P_Cfg9_SW_Ver_Byte11_45 : 16|8@1+ (1,0) [0|255] ""  PC
 SG_ S2P_Cfg9_SW_Ver_Byte12_45 : 24|8@1+ (1,0) [0|255] ""  PC
 SG_ S2P_Cfg9_SW_Ver_Byte13_45 : 32|8@1+ (1,0) [0|255] ""  PC
 SG_ S2P_Cfg9_SW_Ver_Byte14_45 : 40|8@1+ (1,0) [0|255] ""  PC
 SG_ S2P_Cfg9_SW_Ver_Byte15_45 : 48|8@1+ (1,0) [0|255] ""  PC
 SG_ S2P_Cfg9_SW_Ver_Byte16_45 : 56|8@1+ (1,0) [0|255] ""  PC

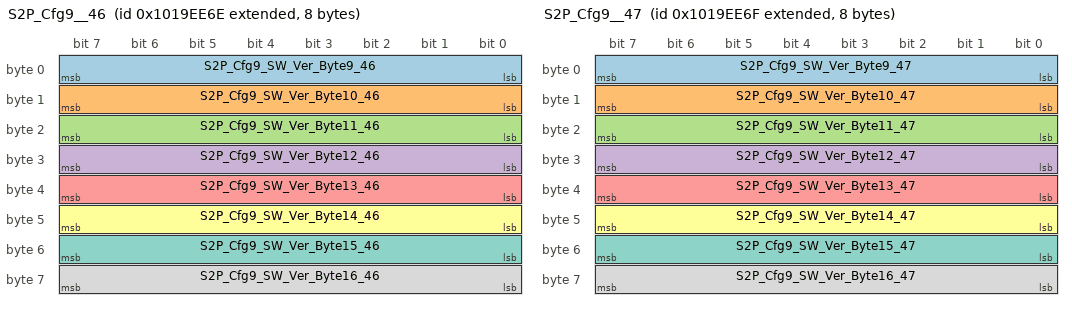
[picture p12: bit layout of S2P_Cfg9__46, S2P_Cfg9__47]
BO_ 2417618542 S2P_Cfg9__46: 8 SBMU
 SG_ S2P_Cfg9_SW_Ver_Byte9_46 : 0|8@1+ (1,0) [0|255] ""  PC
 SG_ S2P_Cfg9_SW_Ver_Byte10_46 : 8|8@1+ (1,0) [0|255] ""  PC
 SG_ S2P_Cfg9_SW_Ver_Byte11_46 : 16|8@1+ (1,0) [0|255] ""  PC
 SG_ S2P_Cfg9_SW_Ver_Byte12_46 : 24|8@1+ (1,0) [0|255] ""  PC
 SG_ S2P_Cfg9_SW_Ver_Byte13_46 : 32|8@1+ (1,0) [0|255] ""  PC
 SG_ S2P_Cfg9_SW_Ver_Byte14_46 : 40|8@1+ (1,0) [0|255] ""  PC
 SG_ S2P_Cfg9_SW_Ver_Byte15_46 : 48|8@1+ (1,0) [0|255] ""  PC
 SG_ S2P_Cfg9_SW_Ver_Byte16_46 : 56|8@1+ (1,0) [0|255] ""  PC

BO_ 2417618543 S2P_Cfg9__47: 8 SBMU
 SG_ S2P_Cfg9_SW_Ver_Byte9_47 : 0|8@1+ (1,0) [0|255] ""  PC
 SG_ S2P_Cfg9_SW_Ver_Byte10_47 : 8|8@1+ (1,0) [0|255] ""  PC
 SG_ S2P_Cfg9_SW_Ver_Byte11_47 : 16|8@1+ (1,0) [0|255] ""  PC
 SG_ S2P_Cfg9_SW_Ver_Byte12_47 : 24|8@1+ (1,0) [0|255] ""  PC
 SG_ S2P_Cfg9_SW_Ver_Byte13_47 : 32|8@1+ (1,0) [0|255] ""  PC
 SG_ S2P_Cfg9_SW_Ver_Byte14_47 : 40|8@1+ (1,0) [0|255] ""  PC
 SG_ S2P_Cfg9_SW_Ver_Byte15_47 : 48|8@1+ (1,0) [0|255] ""  PC
 SG_ S2P_Cfg9_SW_Ver_Byte16_47 : 56|8@1+ (1,0) [0|255] ""  PC

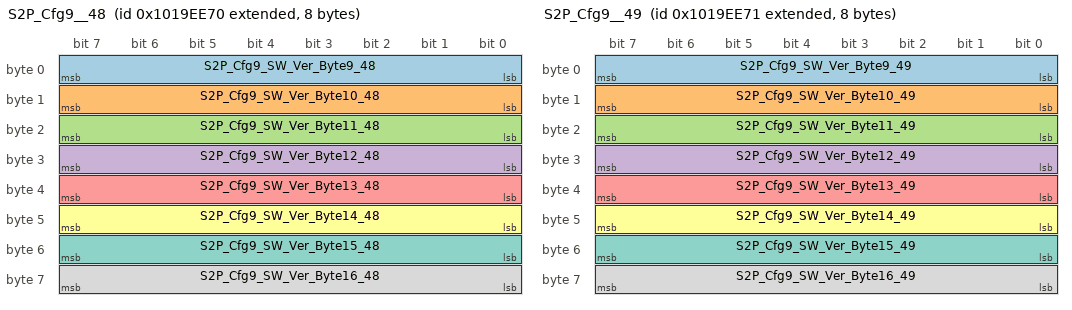
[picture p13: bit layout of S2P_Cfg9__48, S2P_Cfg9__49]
BO_ 2417618544 S2P_Cfg9__48: 8 SBMU
 SG_ S2P_Cfg9_SW_Ver_Byte9_48 : 0|8@1+ (1,0) [0|255] ""  PC
 SG_ S2P_Cfg9_SW_Ver_Byte10_48 : 8|8@1+ (1,0) [0|255] ""  PC
 SG_ S2P_Cfg9_SW_Ver_Byte11_48 : 16|8@1+ (1,0) [0|255] ""  PC
 SG_ S2P_Cfg9_SW_Ver_Byte12_48 : 24|8@1+ (1,0) [0|255] ""  PC
 SG_ S2P_Cfg9_SW_Ver_Byte13_48 : 32|8@1+ (1,0) [0|255] ""  PC
 SG_ S2P_Cfg9_SW_Ver_Byte14_48 : 40|8@1+ (1,0) [0|255] ""  PC
 SG_ S2P_Cfg9_SW_Ver_Byte15_48 : 48|8@1+ (1,0) [0|255] ""  PC
 SG_ S2P_Cfg9_SW_Ver_Byte16_48 : 56|8@1+ (1,0) [0|255] ""  PC

BO_ 2417618545 S2P_Cfg9__49: 8 SBMU
 SG_ S2P_Cfg9_SW_Ver_Byte9_49 : 0|8@1+ (1,0) [0|255] ""  PC
 SG_ S2P_Cfg9_SW_Ver_Byte10_49 : 8|8@1+ (1,0) [0|255] ""  PC
 SG_ S2P_Cfg9_SW_Ver_Byte11_49 : 16|8@1+ (1,0) [0|255] ""  PC
 SG_ S2P_Cfg9_SW_Ver_Byte12_49 : 24|8@1+ (1,0) [0|255] ""  PC
 SG_ S2P_Cfg9_SW_Ver_Byte13_49 : 32|8@1+ (1,0) [0|255] ""  PC
 SG_ S2P_Cfg9_SW_Ver_Byte14_49 : 40|8@1+ (1,0) [0|255] ""  PC
 SG_ S2P_Cfg9_SW_Ver_Byte15_49 : 48|8@1+ (1,0) [0|255] ""  PC
 SG_ S2P_Cfg9_SW_Ver_Byte16_49 : 56|8@1+ (1,0) [0|255] ""  PC

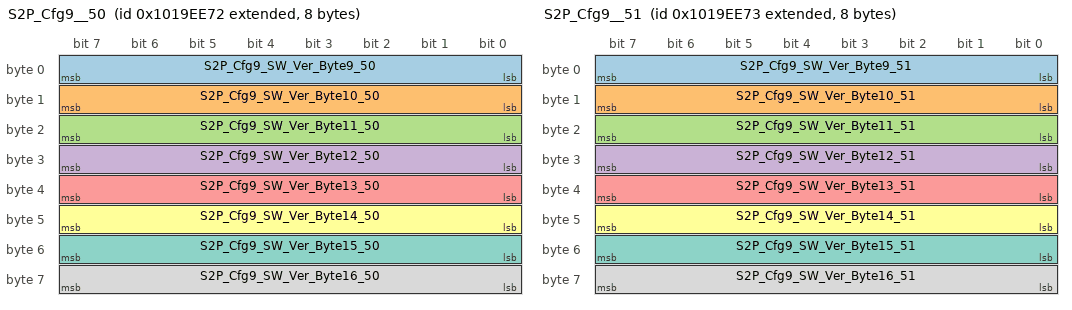
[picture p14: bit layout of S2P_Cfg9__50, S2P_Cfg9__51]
BO_ 2417618546 S2P_Cfg9__50: 8 SBMU
 SG_ S2P_Cfg9_SW_Ver_Byte9_50 : 0|8@1+ (1,0) [0|255] ""  PC
 SG_ S2P_Cfg9_SW_Ver_Byte10_50 : 8|8@1+ (1,0) [0|255] ""  PC
 SG_ S2P_Cfg9_SW_Ver_Byte11_50 : 16|8@1+ (1,0) [0|255] ""  PC
 SG_ S2P_Cfg9_SW_Ver_Byte12_50 : 24|8@1+ (1,0) [0|255] ""  PC
 SG_ S2P_Cfg9_SW_Ver_Byte13_50 : 32|8@1+ (1,0) [0|255] ""  PC
 SG_ S2P_Cfg9_SW_Ver_Byte14_50 : 40|8@1+ (1,0) [0|255] ""  PC
 SG_ S2P_Cfg9_SW_Ver_Byte15_50 : 48|8@1+ (1,0) [0|255] ""  PC
 SG_ S2P_Cfg9_SW_Ver_Byte16_50 : 56|8@1+ (1,0) [0|255] ""  PC

BO_ 2417618547 S2P_Cfg9__51: 8 SBMU
 SG_ S2P_Cfg9_SW_Ver_Byte9_51 : 0|8@1+ (1,0) [0|255] ""  PC
 SG_ S2P_Cfg9_SW_Ver_Byte10_51 : 8|8@1+ (1,0) [0|255] ""  PC
 SG_ S2P_Cfg9_SW_Ver_Byte11_51 : 16|8@1+ (1,0) [0|255] ""  PC
 SG_ S2P_Cfg9_SW_Ver_Byte12_51 : 24|8@1+ (1,0) [0|255] ""  PC
 SG_ S2P_Cfg9_SW_Ver_Byte13_51 : 32|8@1+ (1,0) [0|255] ""  PC
 SG_ S2P_Cfg9_SW_Ver_Byte14_51 : 40|8@1+ (1,0) [0|255] ""  PC
 SG_ S2P_Cfg9_SW_Ver_Byte15_51 : 48|8@1+ (1,0) [0|255] ""  PC
 SG_ S2P_Cfg9_SW_Ver_Byte16_51 : 56|8@1+ (1,0) [0|255] ""  PC

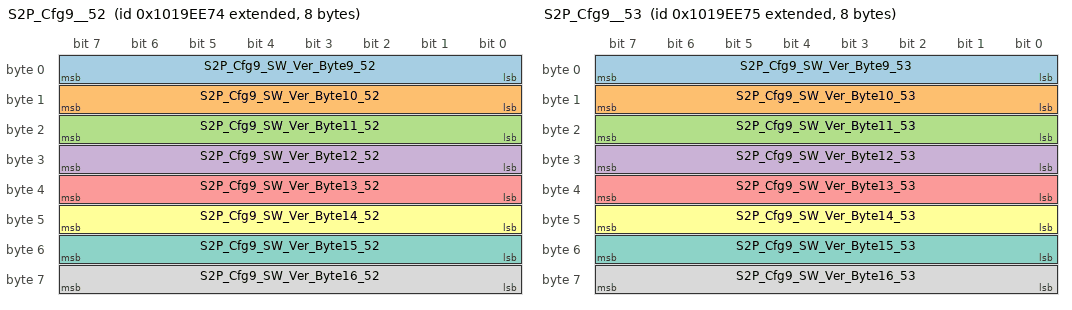
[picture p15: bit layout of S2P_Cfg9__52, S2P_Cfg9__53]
BO_ 2417618548 S2P_Cfg9__52: 8 SBMU
 SG_ S2P_Cfg9_SW_Ver_Byte9_52 : 0|8@1+ (1,0) [0|255] ""  PC
 SG_ S2P_Cfg9_SW_Ver_Byte10_52 : 8|8@1+ (1,0) [0|255] ""  PC
 SG_ S2P_Cfg9_SW_Ver_Byte11_52 : 16|8@1+ (1,0) [0|255] ""  PC
 SG_ S2P_Cfg9_SW_Ver_Byte12_52 : 24|8@1+ (1,0) [0|255] ""  PC
 SG_ S2P_Cfg9_SW_Ver_Byte13_52 : 32|8@1+ (1,0) [0|255] ""  PC
 SG_ S2P_Cfg9_SW_Ver_Byte14_52 : 40|8@1+ (1,0) [0|255] ""  PC
 SG_ S2P_Cfg9_SW_Ver_Byte15_52 : 48|8@1+ (1,0) [0|255] ""  PC
 SG_ S2P_Cfg9_SW_Ver_Byte16_52 : 56|8@1+ (1,0) [0|255] ""  PC

BO_ 2417618549 S2P_Cfg9__53: 8 SBMU
 SG_ S2P_Cfg9_SW_Ver_Byte9_53 : 0|8@1+ (1,0) [0|255] ""  PC
 SG_ S2P_Cfg9_SW_Ver_Byte10_53 : 8|8@1+ (1,0) [0|255] ""  PC
 SG_ S2P_Cfg9_SW_Ver_Byte11_53 : 16|8@1+ (1,0) [0|255] ""  PC
 SG_ S2P_Cfg9_SW_Ver_Byte12_53 : 24|8@1+ (1,0) [0|255] ""  PC
 SG_ S2P_Cfg9_SW_Ver_Byte13_53 : 32|8@1+ (1,0) [0|255] ""  PC
 SG_ S2P_Cfg9_SW_Ver_Byte14_53 : 40|8@1+ (1,0) [0|255] ""  PC
 SG_ S2P_Cfg9_SW_Ver_Byte15_53 : 48|8@1+ (1,0) [0|255] ""  PC
 SG_ S2P_Cfg9_SW_Ver_Byte16_53 : 56|8@1+ (1,0) [0|255] ""  PC

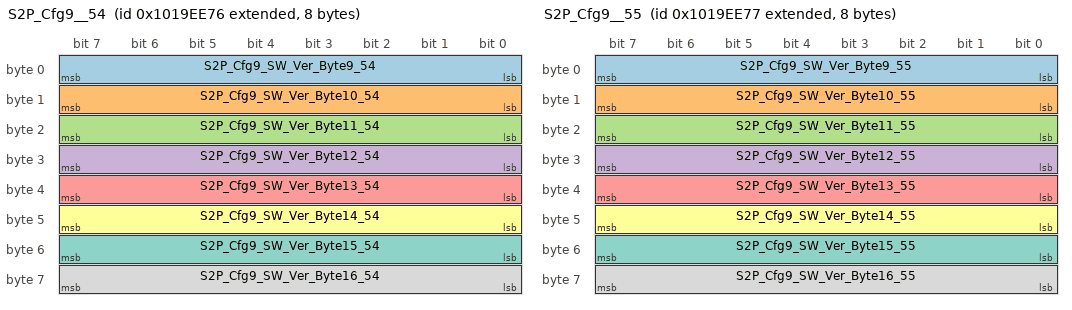
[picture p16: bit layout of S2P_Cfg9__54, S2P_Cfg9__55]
BO_ 2417618550 S2P_Cfg9__54: 8 SBMU
 SG_ S2P_Cfg9_SW_Ver_Byte9_54 : 0|8@1+ (1,0) [0|255] ""  PC
 SG_ S2P_Cfg9_SW_Ver_Byte10_54 : 8|8@1+ (1,0) [0|255] ""  PC
 SG_ S2P_Cfg9_SW_Ver_Byte11_54 : 16|8@1+ (1,0) [0|255] ""  PC
 SG_ S2P_Cfg9_SW_Ver_Byte12_54 : 24|8@1+ (1,0) [0|255] ""  PC
 SG_ S2P_Cfg9_SW_Ver_Byte13_54 : 32|8@1+ (1,0) [0|255] ""  PC
 SG_ S2P_Cfg9_SW_Ver_Byte14_54 : 40|8@1+ (1,0) [0|255] ""  PC
 SG_ S2P_Cfg9_SW_Ver_Byte15_54 : 48|8@1+ (1,0) [0|255] ""  PC
 SG_ S2P_Cfg9_SW_Ver_Byte16_54 : 56|8@1+ (1,0) [0|255] ""  PC

BO_ 2417618551 S2P_Cfg9__55: 8 SBMU
 SG_ S2P_Cfg9_SW_Ver_Byte9_55 : 0|8@1+ (1,0) [0|255] ""  PC
 SG_ S2P_Cfg9_SW_Ver_Byte10_55 : 8|8@1+ (1,0) [0|255] ""  PC
 SG_ S2P_Cfg9_SW_Ver_Byte11_55 : 16|8@1+ (1,0) [0|255] ""  PC
 SG_ S2P_Cfg9_SW_Ver_Byte12_55 : 24|8@1+ (1,0) [0|255] ""  PC
 SG_ S2P_Cfg9_SW_Ver_Byte13_55 : 32|8@1+ (1,0) [0|255] ""  PC
 SG_ S2P_Cfg9_SW_Ver_Byte14_55 : 40|8@1+ (1,0) [0|255] ""  PC
 SG_ S2P_Cfg9_SW_Ver_Byte15_55 : 48|8@1+ (1,0) [0|255] ""  PC
 SG_ S2P_Cfg9_SW_Ver_Byte16_55 : 56|8@1+ (1,0) [0|255] ""  PC

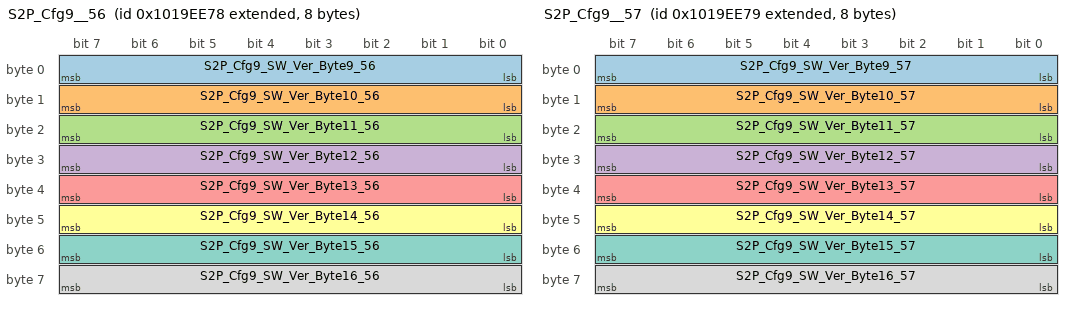
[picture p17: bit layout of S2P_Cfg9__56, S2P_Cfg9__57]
BO_ 2417618552 S2P_Cfg9__56: 8 SBMU
 SG_ S2P_Cfg9_SW_Ver_Byte9_56 : 0|8@1+ (1,0) [0|255] ""  PC
 SG_ S2P_Cfg9_SW_Ver_Byte10_56 : 8|8@1+ (1,0) [0|255] ""  PC
 SG_ S2P_Cfg9_SW_Ver_Byte11_56 : 16|8@1+ (1,0) [0|255] ""  PC
 SG_ S2P_Cfg9_SW_Ver_Byte12_56 : 24|8@1+ (1,0) [0|255] ""  PC
 SG_ S2P_Cfg9_SW_Ver_Byte13_56 : 32|8@1+ (1,0) [0|255] ""  PC
 SG_ S2P_Cfg9_SW_Ver_Byte14_56 : 40|8@1+ (1,0) [0|255] ""  PC
 SG_ S2P_Cfg9_SW_Ver_Byte15_56 : 48|8@1+ (1,0) [0|255] ""  PC
 SG_ S2P_Cfg9_SW_Ver_Byte16_56 : 56|8@1+ (1,0) [0|255] ""  PC

BO_ 2417618553 S2P_Cfg9__57: 8 SBMU
 SG_ S2P_Cfg9_SW_Ver_Byte9_57 : 0|8@1+ (1,0) [0|255] ""  PC
 SG_ S2P_Cfg9_SW_Ver_Byte10_57 : 8|8@1+ (1,0) [0|255] ""  PC
 SG_ S2P_Cfg9_SW_Ver_Byte11_57 : 16|8@1+ (1,0) [0|255] ""  PC
 SG_ S2P_Cfg9_SW_Ver_Byte12_57 : 24|8@1+ (1,0) [0|255] ""  PC
 SG_ S2P_Cfg9_SW_Ver_Byte13_57 : 32|8@1+ (1,0) [0|255] ""  PC
 SG_ S2P_Cfg9_SW_Ver_Byte14_57 : 40|8@1+ (1,0) [0|255] ""  PC
 SG_ S2P_Cfg9_SW_Ver_Byte15_57 : 48|8@1+ (1,0) [0|255] ""  PC
 SG_ S2P_Cfg9_SW_Ver_Byte16_57 : 56|8@1+ (1,0) [0|255] ""  PC

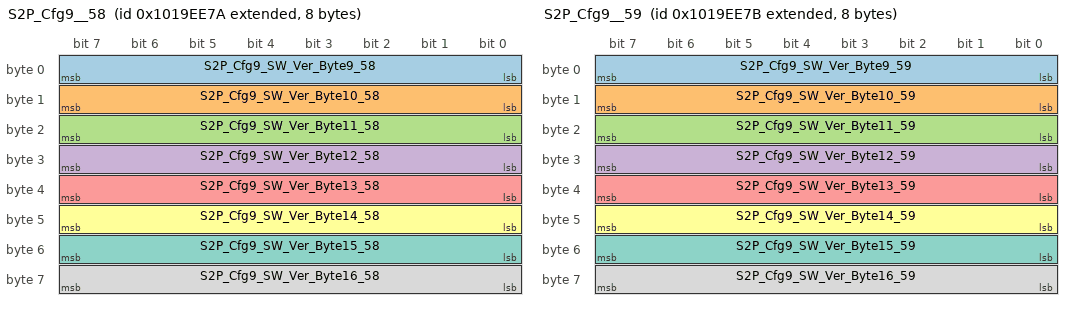
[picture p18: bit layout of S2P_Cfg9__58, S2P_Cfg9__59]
BO_ 2417618554 S2P_Cfg9__58: 8 SBMU
 SG_ S2P_Cfg9_SW_Ver_Byte9_58 : 0|8@1+ (1,0) [0|255] ""  PC
 SG_ S2P_Cfg9_SW_Ver_Byte10_58 : 8|8@1+ (1,0) [0|255] ""  PC
 SG_ S2P_Cfg9_SW_Ver_Byte11_58 : 16|8@1+ (1,0) [0|255] ""  PC
 SG_ S2P_Cfg9_SW_Ver_Byte12_58 : 24|8@1+ (1,0) [0|255] ""  PC
 SG_ S2P_Cfg9_SW_Ver_Byte13_58 : 32|8@1+ (1,0) [0|255] ""  PC
 SG_ S2P_Cfg9_SW_Ver_Byte14_58 : 40|8@1+ (1,0) [0|255] ""  PC
 SG_ S2P_Cfg9_SW_Ver_Byte15_58 : 48|8@1+ (1,0) [0|255] ""  PC
 SG_ S2P_Cfg9_SW_Ver_Byte16_58 : 56|8@1+ (1,0) [0|255] ""  PC

BO_ 2417618555 S2P_Cfg9__59: 8 SBMU
 SG_ S2P_Cfg9_SW_Ver_Byte9_59 : 0|8@1+ (1,0) [0|255] ""  PC
 SG_ S2P_Cfg9_SW_Ver_Byte10_59 : 8|8@1+ (1,0) [0|255] ""  PC
 SG_ S2P_Cfg9_SW_Ver_Byte11_59 : 16|8@1+ (1,0) [0|255] ""  PC
 SG_ S2P_Cfg9_SW_Ver_Byte12_59 : 24|8@1+ (1,0) [0|255] ""  PC
 SG_ S2P_Cfg9_SW_Ver_Byte13_59 : 32|8@1+ (1,0) [0|255] ""  PC
 SG_ S2P_Cfg9_SW_Ver_Byte14_59 : 40|8@1+ (1,0) [0|255] ""  PC
 SG_ S2P_Cfg9_SW_Ver_Byte15_59 : 48|8@1+ (1,0) [0|255] ""  PC
 SG_ S2P_Cfg9_SW_Ver_Byte16_59 : 56|8@1+ (1,0) [0|255] ""  PC

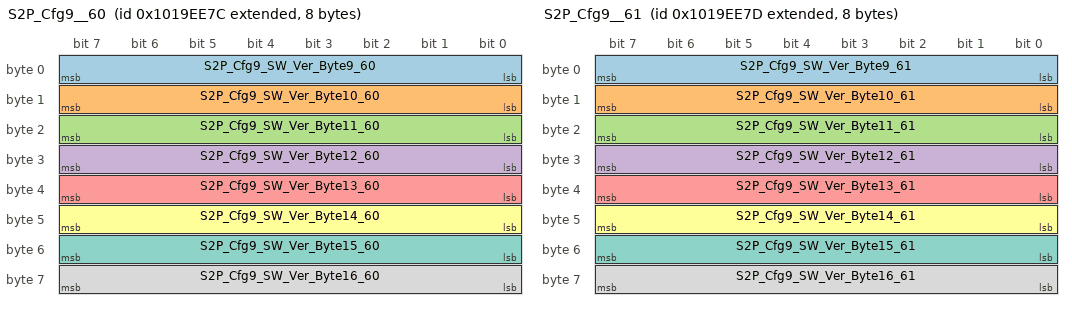
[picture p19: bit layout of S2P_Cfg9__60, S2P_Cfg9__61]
BO_ 2417618556 S2P_Cfg9__60: 8 SBMU
 SG_ S2P_Cfg9_SW_Ver_Byte9_60 : 0|8@1+ (1,0) [0|255] ""  PC
 SG_ S2P_Cfg9_SW_Ver_Byte10_60 : 8|8@1+ (1,0) [0|255] ""  PC
 SG_ S2P_Cfg9_SW_Ver_Byte11_60 : 16|8@1+ (1,0) [0|255] ""  PC
 SG_ S2P_Cfg9_SW_Ver_Byte12_60 : 24|8@1+ (1,0) [0|255] ""  PC
 SG_ S2P_Cfg9_SW_Ver_Byte13_60 : 32|8@1+ (1,0) [0|255] ""  PC
 SG_ S2P_Cfg9_SW_Ver_Byte14_60 : 40|8@1+ (1,0) [0|255] ""  PC
 SG_ S2P_Cfg9_SW_Ver_Byte15_60 : 48|8@1+ (1,0) [0|255] ""  PC
 SG_ S2P_Cfg9_SW_Ver_Byte16_60 : 56|8@1+ (1,0) [0|255] ""  PC

BO_ 2417618557 S2P_Cfg9__61: 8 SBMU
 SG_ S2P_Cfg9_SW_Ver_Byte9_61 : 0|8@1+ (1,0) [0|255] ""  PC
 SG_ S2P_Cfg9_SW_Ver_Byte10_61 : 8|8@1+ (1,0) [0|255] ""  PC
 SG_ S2P_Cfg9_SW_Ver_Byte11_61 : 16|8@1+ (1,0) [0|255] ""  PC
 SG_ S2P_Cfg9_SW_Ver_Byte12_61 : 24|8@1+ (1,0) [0|255] ""  PC
 SG_ S2P_Cfg9_SW_Ver_Byte13_61 : 32|8@1+ (1,0) [0|255] ""  PC
 SG_ S2P_Cfg9_SW_Ver_Byte14_61 : 40|8@1+ (1,0) [0|255] ""  PC
 SG_ S2P_Cfg9_SW_Ver_Byte15_61 : 48|8@1+ (1,0) [0|255] ""  PC
 SG_ S2P_Cfg9_SW_Ver_Byte16_61 : 56|8@1+ (1,0) [0|255] ""  PC

BO_ 2417618558 S2P_Cfg9__62: 8 SBMU
 SG_ S2P_Cfg9_SW_Ver_Byte9_62 : 0|8@1+ (1,0) [0|255] ""  PC
 SG_ S2P_Cfg9_SW_Ver_Byte10_62 : 8|8@1+ (1,0) [0|255] ""  PC
 SG_ S2P_Cfg9_SW_Ver_Byte11_62 : 16|8@1+ (1,0) [0|255] ""  PC
 SG_ S2P_Cfg9_SW_Ver_Byte12_62 : 24|8@1+ (1,0) [0|255] ""  PC
 SG_ S2P_Cfg9_SW_Ver_Byte13_62 : 32|8@1+ (1,0) [0|255] ""  PC
 SG_ S2P_Cfg9_SW_Ver_Byte14_62 : 40|8@1+ (1,0) [0|255] ""  PC
 SG_ S2P_Cfg9_SW_Ver_Byte15_62 : 48|8@1+ (1,0) [0|255] ""  PC
 SG_ S2P_Cfg9_SW_Ver_Byte16_62 : 56|8@1+ (1,0) [0|255] ""  PC

BO_ 2417618559 S2P_Cfg9__63: 8 SBMU
 SG_ S2P_Cfg9_SW_Ver_Byte9_63 : 0|8@1+ (1,0) [0|255] ""  PC
 SG_ S2P_Cfg9_SW_Ver_Byte10_63 : 8|8@1+ (1,0) [0|255] ""  PC
 SG_ S2P_Cfg9_SW_Ver_Byte11_63 : 16|8@1+ (1,0) [0|255] ""  PC
 SG_ S2P_Cfg9_SW_Ver_Byte12_63 : 24|8@1+ (1,0) [0|255] ""  PC
 SG_ S2P_Cfg9_SW_Ver_Byte13_63 : 32|8@1+ (1,0) [0|255] ""  PC
 SG_ S2P_Cfg9_SW_Ver_Byte14_63 : 40|8@1+ (1,0) [0|255] ""  PC
 SG_ S2P_Cfg9_SW_Ver_Byte15_63 : 48|8@1+ (1,0) [0|255] ""  PC
 SG_ S2P_Cfg9_SW_Ver_Byte16_63 : 56|8@1+ (1,0) [0|255] ""  PC

BO_ 2417684033 S2P_Cfg10__01: 8 SBMU
 SG_ S2P_Cfg10_HW_Ver_Byte1_01 : 0|8@1+ (1,0) [0|255] ""  PC
 SG_ S2P_Cfg10_HW_Ver_Byte2_01 : 8|8@1+ (1,0) [0|255] ""  PC
 SG_ S2P_Cfg10_HW_Ver_Byte3_01 : 16|8@1+ (1,0) [0|255] ""  PC
 SG_ S2P_Cfg10_HW_Ver_Byte4_01 : 24|8@1+ (1,0) [0|255] ""  PC
 SG_ S2P_Cfg10_HW_Ver_Byte5_01 : 32|8@1+ (1,0) [0|255] ""  PC
 SG_ S2P_Cfg10_HW_Ver_Byte6_01 : 40|8@1+ (1,0) [0|255] ""  PC
 SG_ S2P_Cfg10_HW_Ver_Byte7_01 : 48|8@1+ (1,0) [0|255] ""  PC
 SG_ S2P_Cfg10_HW_Ver_Byte8_01 : 56|8@1+ (1,0) [0|255] ""  PC

BO_ 2417684034 S2P_Cfg10__02: 8 SBMU
 SG_ S2P_Cfg10_HW_Ver_Byte1_02 : 0|8@1+ (1,0) [0|255] ""  PC
 SG_ S2P_Cfg10_HW_Ver_Byte2_02 : 8|8@1+ (1,0) [0|255] ""  PC
 SG_ S2P_Cfg10_HW_Ver_Byte3_02 : 16|8@1+ (1,0) [0|255] ""  PC
 SG_ S2P_Cfg10_HW_Ver_Byte4_02 : 24|8@1+ (1,0) [0|255] ""  PC
 SG_ S2P_Cfg10_HW_Ver_Byte5_02 : 32|8@1+ (1,0) [0|255] ""  PC
 SG_ S2P_Cfg10_HW_Ver_Byte6_02 : 40|8@1+ (1,0) [0|255] ""  PC
 SG_ S2P_Cfg10_HW_Ver_Byte7_02 : 48|8@1+ (1,0) [0|255] ""  PC
 SG_ S2P_Cfg10_HW_Ver_Byte8_02 : 56|8@1+ (1,0) [0|255] ""  PC

BO_ 2417684035 S2P_Cfg10__03: 8 SBMU
 SG_ S2P_Cfg10_HW_Ver_Byte1_03 : 0|8@1+ (1,0) [0|255] ""  PC
 SG_ S2P_Cfg10_HW_Ver_Byte2_03 : 8|8@1+ (1,0) [0|255] ""  PC
 SG_ S2P_Cfg10_HW_Ver_Byte3_03 : 16|8@1+ (1,0) [0|255] ""  PC
 SG_ S2P_Cfg10_HW_Ver_Byte4_03 : 24|8@1+ (1,0) [0|255] ""  PC
 SG_ S2P_Cfg10_HW_Ver_Byte5_03 : 32|8@1+ (1,0) [0|255] ""  PC
 SG_ S2P_Cfg10_HW_Ver_Byte6_03 : 40|8@1+ (1,0) [0|255] ""  PC
 SG_ S2P_Cfg10_HW_Ver_Byte7_03 : 48|8@1+ (1,0) [0|255] ""  PC
 SG_ S2P_Cfg10_HW_Ver_Byte8_03 : 56|8@1+ (1,0) [0|255] ""  PC

BO_ 2417684036 S2P_Cfg10__04: 8 SBMU
 SG_ S2P_Cfg10_HW_Ver_Byte1_04 : 0|8@1+ (1,0) [0|255] ""  PC
 SG_ S2P_Cfg10_HW_Ver_Byte2_04 : 8|8@1+ (1,0) [0|255] ""  PC
 SG_ S2P_Cfg10_HW_Ver_Byte3_04 : 16|8@1+ (1,0) [0|255] ""  PC
 SG_ S2P_Cfg10_HW_Ver_Byte4_04 : 24|8@1+ (1,0) [0|255] ""  PC
 SG_ S2P_Cfg10_HW_Ver_Byte5_04 : 32|8@1+ (1,0) [0|255] ""  PC
 SG_ S2P_Cfg10_HW_Ver_Byte6_04 : 40|8@1+ (1,0) [0|255] ""  PC
 SG_ S2P_Cfg10_HW_Ver_Byte7_04 : 48|8@1+ (1,0) [0|255] ""  PC
 SG_ S2P_Cfg10_HW_Ver_Byte8_04 : 56|8@1+ (1,0) [0|255] ""  PC

BO_ 2417684037 S2P_Cfg10__05: 8 SBMU
 SG_ S2P_Cfg10_HW_Ver_Byte1_05 : 0|8@1+ (1,0) [0|255] ""  PC
 SG_ S2P_Cfg10_HW_Ver_Byte2_05 : 8|8@1+ (1,0) [0|255] ""  PC
 SG_ S2P_Cfg10_HW_Ver_Byte3_05 : 16|8@1+ (1,0) [0|255] ""  PC
 SG_ S2P_Cfg10_HW_Ver_Byte4_05 : 24|8@1+ (1,0) [0|255] ""  PC
 SG_ S2P_Cfg10_HW_Ver_Byte5_05 : 32|8@1+ (1,0) [0|255] ""  PC
 SG_ S2P_Cfg10_HW_Ver_Byte6_05 : 40|8@1+ (1,0) [0|255] ""  PC
 SG_ S2P_Cfg10_HW_Ver_Byte7_05 : 48|8@1+ (1,0) [0|255] ""  PC
 SG_ S2P_Cfg10_HW_Ver_Byte8_05 : 56|8@1+ (1,0) [0|255] ""  PC

BO_ 2417684038 S2P_Cfg10__06: 8 SBMU
 SG_ S2P_Cfg10_HW_Ver_Byte1_06 : 0|8@1+ (1,0) [0|255] ""  PC
 SG_ S2P_Cfg10_HW_Ver_Byte2_06 : 8|8@1+ (1,0) [0|255] ""  PC
 SG_ S2P_Cfg10_HW_Ver_Byte3_06 : 16|8@1+ (1,0) [0|255] ""  PC
 SG_ S2P_Cfg10_HW_Ver_Byte4_06 : 24|8@1+ (1,0) [0|255] ""  PC
 SG_ S2P_Cfg10_HW_Ver_Byte5_06 : 32|8@1+ (1,0) [0|255] ""  PC
 SG_ S2P_Cfg10_HW_Ver_Byte6_06 : 40|8@1+ (1,0) [0|255] ""  PC
 SG_ S2P_Cfg10_HW_Ver_Byte7_06 : 48|8@1+ (1,0) [0|255] ""  PC
 SG_ S2P_Cfg10_HW_Ver_Byte8_06 : 56|8@1+ (1,0) [0|255] ""  PC

BO_ 2417684039 S2P_Cfg10__07: 8 SBMU
 SG_ S2P_Cfg10_HW_Ver_Byte1_07 : 0|8@1+ (1,0) [0|255] ""  PC
 SG_ S2P_Cfg10_HW_Ver_Byte2_07 : 8|8@1+ (1,0) [0|255] ""  PC
 SG_ S2P_Cfg10_HW_Ver_Byte3_07 : 16|8@1+ (1,0) [0|255] ""  PC
 SG_ S2P_Cfg10_HW_Ver_Byte4_07 : 24|8@1+ (1,0) [0|255] ""  PC
 SG_ S2P_Cfg10_HW_Ver_Byte5_07 : 32|8@1+ (1,0) [0|255] ""  PC
 SG_ S2P_Cfg10_HW_Ver_Byte6_07 : 40|8@1+ (1,0) [0|255] ""  PC
 SG_ S2P_Cfg10_HW_Ver_Byte7_07 : 48|8@1+ (1,0) [0|255] ""  PC
 SG_ S2P_Cfg10_HW_Ver_Byte8_07 : 56|8@1+ (1,0) [0|255] ""  PC

BO_ 2417684040 S2P_Cfg10__08: 8 SBMU
 SG_ S2P_Cfg10_HW_Ver_Byte1_08 : 0|8@1+ (1,0) [0|255] ""  PC
 SG_ S2P_Cfg10_HW_Ver_Byte2_08 : 8|8@1+ (1,0) [0|255] ""  PC
 SG_ S2P_Cfg10_HW_Ver_Byte3_08 : 16|8@1+ (1,0) [0|255] ""  PC
 SG_ S2P_Cfg10_HW_Ver_Byte4_08 : 24|8@1+ (1,0) [0|255] ""  PC
 SG_ S2P_Cfg10_HW_Ver_Byte5_08 : 32|8@1+ (1,0) [0|255] ""  PC
 SG_ S2P_Cfg10_HW_Ver_Byte6_08 : 40|8@1+ (1,0) [0|255] ""  PC
 SG_ S2P_Cfg10_HW_Ver_Byte7_08 : 48|8@1+ (1,0) [0|255] ""  PC
 SG_ S2P_Cfg10_HW_Ver_Byte8_08 : 56|8@1+ (1,0) [0|255] ""  PC

BO_ 2417684041 S2P_Cfg10__09: 8 SBMU
 SG_ S2P_Cfg10_HW_Ver_Byte1_09 : 0|8@1+ (1,0) [0|255] ""  PC
 SG_ S2P_Cfg10_HW_Ver_Byte2_09 : 8|8@1+ (1,0) [0|255] ""  PC
 SG_ S2P_Cfg10_HW_Ver_Byte3_09 : 16|8@1+ (1,0) [0|255] ""  PC
 SG_ S2P_Cfg10_HW_Ver_Byte4_09 : 24|8@1+ (1,0) [0|255] ""  PC
 SG_ S2P_Cfg10_HW_Ver_Byte5_09 : 32|8@1+ (1,0) [0|255] ""  PC
 SG_ S2P_Cfg10_HW_Ver_Byte6_09 : 40|8@1+ (1,0) [0|255] ""  PC
 SG_ S2P_Cfg10_HW_Ver_Byte7_09 : 48|8@1+ (1,0) [0|255] ""  PC
 SG_ S2P_Cfg10_HW_Ver_Byte8_09 : 56|8@1+ (1,0) [0|255] ""  PC

BO_ 2417684042 S2P_Cfg10__10: 8 SBMU
 SG_ S2P_Cfg10_HW_Ver_Byte1_10 : 0|8@1+ (1,0) [0|255] ""  PC
 SG_ S2P_Cfg10_HW_Ver_Byte2_10 : 8|8@1+ (1,0) [0|255] ""  PC
 SG_ S2P_Cfg10_HW_Ver_Byte3_10 : 16|8@1+ (1,0) [0|255] ""  PC
 SG_ S2P_Cfg10_HW_Ver_Byte4_10 : 24|8@1+ (1,0) [0|255] ""  PC
 SG_ S2P_Cfg10_HW_Ver_Byte5_10 : 32|8@1+ (1,0) [0|255] ""  PC
 SG_ S2P_Cfg10_HW_Ver_Byte6_10 : 40|8@1+ (1,0) [0|255] ""  PC
 SG_ S2P_Cfg10_HW_Ver_Byte7_10 : 48|8@1+ (1,0) [0|255] ""  PC
 SG_ S2P_Cfg10_HW_Ver_Byte8_10 : 56|8@1+ (1,0) [0|255] ""  PC

BO_ 2417684043 S2P_Cfg10__11: 8 SBMU
 SG_ S2P_Cfg10_HW_Ver_Byte1_11 : 0|8@1+ (1,0) [0|255] ""  PC
 SG_ S2P_Cfg10_HW_Ver_Byte2_11 : 8|8@1+ (1,0) [0|255] ""  PC
 SG_ S2P_Cfg10_HW_Ver_Byte3_11 : 16|8@1+ (1,0) [0|255] ""  PC
 SG_ S2P_Cfg10_HW_Ver_Byte4_11 : 24|8@1+ (1,0) [0|255] ""  PC
 SG_ S2P_Cfg10_HW_Ver_Byte5_11 : 32|8@1+ (1,0) [0|255] ""  PC
 SG_ S2P_Cfg10_HW_Ver_Byte6_11 : 40|8@1+ (1,0) [0|255] ""  PC
 SG_ S2P_Cfg10_HW_Ver_Byte7_11 : 48|8@1+ (1,0) [0|255] ""  PC
 SG_ S2P_Cfg10_HW_Ver_Byte8_11 : 56|8@1+ (1,0) [0|255] ""  PC

BO_ 2417684044 S2P_Cfg10__12: 8 SBMU
 SG_ S2P_Cfg10_HW_Ver_Byte1_12 : 0|8@1+ (1,0) [0|255] ""  PC
 SG_ S2P_Cfg10_HW_Ver_Byte2_12 : 8|8@1+ (1,0) [0|255] ""  PC
 SG_ S2P_Cfg10_HW_Ver_Byte3_12 : 16|8@1+ (1,0) [0|255] ""  PC
 SG_ S2P_Cfg10_HW_Ver_Byte4_12 : 24|8@1+ (1,0) [0|255] ""  PC
 SG_ S2P_Cfg10_HW_Ver_Byte5_12 : 32|8@1+ (1,0) [0|255] ""  PC
 SG_ S2P_Cfg10_HW_Ver_Byte6_12 : 40|8@1+ (1,0) [0|255] ""  PC
 SG_ S2P_Cfg10_HW_Ver_Byte7_12 : 48|8@1+ (1,0) [0|255] ""  PC
 SG_ S2P_Cfg10_HW_Ver_Byte8_12 : 56|8@1+ (1,0) [0|255] ""  PC

BO_ 2417684045 S2P_Cfg10__13: 8 SBMU
 SG_ S2P_Cfg10_HW_Ver_Byte1_13 : 0|8@1+ (1,0) [0|255] ""  PC
 SG_ S2P_Cfg10_HW_Ver_Byte2_13 : 8|8@1+ (1,0) [0|255] ""  PC
 SG_ S2P_Cfg10_HW_Ver_Byte3_13 : 16|8@1+ (1,0) [0|255] ""  PC
 SG_ S2P_Cfg10_HW_Ver_Byte4_13 : 24|8@1+ (1,0) [0|255] ""  PC
 SG_ S2P_Cfg10_HW_Ver_Byte5_13 : 32|8@1+ (1,0) [0|255] ""  PC
 SG_ S2P_Cfg10_HW_Ver_Byte6_13 : 40|8@1+ (1,0) [0|255] ""  PC
 SG_ S2P_Cfg10_HW_Ver_Byte7_13 : 48|8@1+ (1,0) [0|255] ""  PC
 SG_ S2P_Cfg10_HW_Ver_Byte8_13 : 56|8@1+ (1,0) [0|255] ""  PC

BO_ 2417684046 S2P_Cfg10__14: 8 SBMU
 SG_ S2P_Cfg10_HW_Ver_Byte1_14 : 0|8@1+ (1,0) [0|255] ""  PC
 SG_ S2P_Cfg10_HW_Ver_Byte2_14 : 8|8@1+ (1,0) [0|255] ""  PC
 SG_ S2P_Cfg10_HW_Ver_Byte3_14 : 16|8@1+ (1,0) [0|255] ""  PC
 SG_ S2P_Cfg10_HW_Ver_Byte4_14 : 24|8@1+ (1,0) [0|255] ""  PC
 SG_ S2P_Cfg10_HW_Ver_Byte5_14 : 32|8@1+ (1,0) [0|255] ""  PC
 SG_ S2P_Cfg10_HW_Ver_Byte6_14 : 40|8@1+ (1,0) [0|255] ""  PC
 SG_ S2P_Cfg10_HW_Ver_Byte7_14 : 48|8@1+ (1,0) [0|255] ""  PC
 SG_ S2P_Cfg10_HW_Ver_Byte8_14 : 56|8@1+ (1,0) [0|255] ""  PC

BO_ 2417684047 S2P_Cfg10__15: 8 SBMU
 SG_ S2P_Cfg10_HW_Ver_Byte1_15 : 0|8@1+ (1,0) [0|255] ""  PC
 SG_ S2P_Cfg10_HW_Ver_Byte2_15 : 8|8@1+ (1,0) [0|255] ""  PC
 SG_ S2P_Cfg10_HW_Ver_Byte3_15 : 16|8@1+ (1,0) [0|255] ""  PC
 SG_ S2P_Cfg10_HW_Ver_Byte4_15 : 24|8@1+ (1,0) [0|255] ""  PC
 SG_ S2P_Cfg10_HW_Ver_Byte5_15 : 32|8@1+ (1,0) [0|255] ""  PC
 SG_ S2P_Cfg10_HW_Ver_Byte6_15 : 40|8@1+ (1,0) [0|255] ""  PC
 SG_ S2P_Cfg10_HW_Ver_Byte7_15 : 48|8@1+ (1,0) [0|255] ""  PC
 SG_ S2P_Cfg10_HW_Ver_Byte8_15 : 56|8@1+ (1,0) [0|255] ""  PC

BO_ 2417684048 S2P_Cfg10__16: 8 SBMU
 SG_ S2P_Cfg10_HW_Ver_Byte1_16 : 0|8@1+ (1,0) [0|255] ""  PC
 SG_ S2P_Cfg10_HW_Ver_Byte2_16 : 8|8@1+ (1,0) [0|255] ""  PC
 SG_ S2P_Cfg10_HW_Ver_Byte3_16 : 16|8@1+ (1,0) [0|255] ""  PC
 SG_ S2P_Cfg10_HW_Ver_Byte4_16 : 24|8@1+ (1,0) [0|255] ""  PC
 SG_ S2P_Cfg10_HW_Ver_Byte5_16 : 32|8@1+ (1,0) [0|255] ""  PC
 SG_ S2P_Cfg10_HW_Ver_Byte6_16 : 40|8@1+ (1,0) [0|255] ""  PC
 SG_ S2P_Cfg10_HW_Ver_Byte7_16 : 48|8@1+ (1,0) [0|255] ""  PC
 SG_ S2P_Cfg10_HW_Ver_Byte8_16 : 56|8@1+ (1,0) [0|255] ""  PC

BO_ 2417684049 S2P_Cfg10__17: 8 SBMU
 SG_ S2P_Cfg10_HW_Ver_Byte1_17 : 0|8@1+ (1,0) [0|255] ""  PC
 SG_ S2P_Cfg10_HW_Ver_Byte2_17 : 8|8@1+ (1,0) [0|255] ""  PC
 SG_ S2P_Cfg10_HW_Ver_Byte3_17 : 16|8@1+ (1,0) [0|255] ""  PC
 SG_ S2P_Cfg10_HW_Ver_Byte4_17 : 24|8@1+ (1,0) [0|255] ""  PC
 SG_ S2P_Cfg10_HW_Ver_Byte5_17 : 32|8@1+ (1,0) [0|255] ""  PC
 SG_ S2P_Cfg10_HW_Ver_Byte6_17 : 40|8@1+ (1,0) [0|255] ""  PC
 SG_ S2P_Cfg10_HW_Ver_Byte7_17 : 48|8@1+ (1,0) [0|255] ""  PC
 SG_ S2P_Cfg10_HW_Ver_Byte8_17 : 56|8@1+ (1,0) [0|255] ""  PC

BO_ 2417684050 S2P_Cfg10__18: 8 SBMU
 SG_ S2P_Cfg10_HW_Ver_Byte1_18 : 0|8@1+ (1,0) [0|255] ""  PC
 SG_ S2P_Cfg10_HW_Ver_Byte2_18 : 8|8@1+ (1,0) [0|255] ""  PC
 SG_ S2P_Cfg10_HW_Ver_Byte3_18 : 16|8@1+ (1,0) [0|255] ""  PC
 SG_ S2P_Cfg10_HW_Ver_Byte4_18 : 24|8@1+ (1,0) [0|255] ""  PC
 SG_ S2P_Cfg10_HW_Ver_Byte5_18 : 32|8@1+ (1,0) [0|255] ""  PC
 SG_ S2P_Cfg10_HW_Ver_Byte6_18 : 40|8@1+ (1,0) [0|255] ""  PC
 SG_ S2P_Cfg10_HW_Ver_Byte7_18 : 48|8@1+ (1,0) [0|255] ""  PC
 SG_ S2P_Cfg10_HW_Ver_Byte8_18 : 56|8@1+ (1,0) [0|255] ""  PC

BO_ 2417684051 S2P_Cfg10__19: 8 SBMU
 SG_ S2P_Cfg10_HW_Ver_Byte1_19 : 0|8@1+ (1,0) [0|255] ""  PC
 SG_ S2P_Cfg10_HW_Ver_Byte2_19 : 8|8@1+ (1,0) [0|255] ""  PC
 SG_ S2P_Cfg10_HW_Ver_Byte3_19 : 16|8@1+ (1,0) [0|255] ""  PC
 SG_ S2P_Cfg10_HW_Ver_Byte4_19 : 24|8@1+ (1,0) [0|255] ""  PC
 SG_ S2P_Cfg10_HW_Ver_Byte5_19 : 32|8@1+ (1,0) [0|255] ""  PC
 SG_ S2P_Cfg10_HW_Ver_Byte6_19 : 40|8@1+ (1,0) [0|255] ""  PC
 SG_ S2P_Cfg10_HW_Ver_Byte7_19 : 48|8@1+ (1,0) [0|255] ""  PC
 SG_ S2P_Cfg10_HW_Ver_Byte8_19 : 56|8@1+ (1,0) [0|255] ""  PC

BO_ 2417684052 S2P_Cfg10__20: 8 SBMU
 SG_ S2P_Cfg10_HW_Ver_Byte1_20 : 0|8@1+ (1,0) [0|255] ""  PC
 SG_ S2P_Cfg10_HW_Ver_Byte2_20 : 8|8@1+ (1,0) [0|255] ""  PC
 SG_ S2P_Cfg10_HW_Ver_Byte3_20 : 16|8@1+ (1,0) [0|255] ""  PC
 SG_ S2P_Cfg10_HW_Ver_Byte4_20 : 24|8@1+ (1,0) [0|255] ""  PC
 SG_ S2P_Cfg10_HW_Ver_Byte5_20 : 32|8@1+ (1,0) [0|255] ""  PC
 SG_ S2P_Cfg10_HW_Ver_Byte6_20 : 40|8@1+ (1,0) [0|255] ""  PC
 SG_ S2P_Cfg10_HW_Ver_Byte7_20 : 48|8@1+ (1,0) [0|255] ""  PC
 SG_ S2P_Cfg10_HW_Ver_Byte8_20 : 56|8@1+ (1,0) [0|255] ""  PC

BO_ 2417684053 S2P_Cfg10__21: 8 SBMU
 SG_ S2P_Cfg10_HW_Ver_Byte1_21 : 0|8@1+ (1,0) [0|255] ""  PC
 SG_ S2P_Cfg10_HW_Ver_Byte2_21 : 8|8@1+ (1,0) [0|255] ""  PC
 SG_ S2P_Cfg10_HW_Ver_Byte3_21 : 16|8@1+ (1,0) [0|255] ""  PC
 SG_ S2P_Cfg10_HW_Ver_Byte4_21 : 24|8@1+ (1,0) [0|255] ""  PC
 SG_ S2P_Cfg10_HW_Ver_Byte5_21 : 32|8@1+ (1,0) [0|255] ""  PC
 SG_ S2P_Cfg10_HW_Ver_Byte6_21 : 40|8@1+ (1,0) [0|255] ""  PC
 SG_ S2P_Cfg10_HW_Ver_Byte7_21 : 48|8@1+ (1,0) [0|255] ""  PC
 SG_ S2P_Cfg10_HW_Ver_Byte8_21 : 56|8@1+ (1,0) [0|255] ""  PC

BO_ 2417684054 S2P_Cfg10__22: 8 SBMU
 SG_ S2P_Cfg10_HW_Ver_Byte1_22 : 0|8@1+ (1,0) [0|255] ""  PC
 SG_ S2P_Cfg10_HW_Ver_Byte2_22 : 8|8@1+ (1,0) [0|255] ""  PC
 SG_ S2P_Cfg10_HW_Ver_Byte3_22 : 16|8@1+ (1,0) [0|255] ""  PC
 SG_ S2P_Cfg10_HW_Ver_Byte4_22 : 24|8@1+ (1,0) [0|255] ""  PC
 SG_ S2P_Cfg10_HW_Ver_Byte5_22 : 32|8@1+ (1,0) [0|255] ""  PC
 SG_ S2P_Cfg10_HW_Ver_Byte6_22 : 40|8@1+ (1,0) [0|255] ""  PC
 SG_ S2P_Cfg10_HW_Ver_Byte7_22 : 48|8@1+ (1,0) [0|255] ""  PC
 SG_ S2P_Cfg10_HW_Ver_Byte8_22 : 56|8@1+ (1,0) [0|255] ""  PC

BO_ 2417684055 S2P_Cfg10__23: 8 SBMU
 SG_ S2P_Cfg10_HW_Ver_Byte1_23 : 0|8@1+ (1,0) [0|255] ""  PC
 SG_ S2P_Cfg10_HW_Ver_Byte2_23 : 8|8@1+ (1,0) [0|255] ""  PC
 SG_ S2P_Cfg10_HW_Ver_Byte3_23 : 16|8@1+ (1,0) [0|255] ""  PC
 SG_ S2P_Cfg10_HW_Ver_Byte4_23 : 24|8@1+ (1,0) [0|255] ""  PC
 SG_ S2P_Cfg10_HW_Ver_Byte5_23 : 32|8@1+ (1,0) [0|255] ""  PC
 SG_ S2P_Cfg10_HW_Ver_Byte6_23 : 40|8@1+ (1,0) [0|255] ""  PC
 SG_ S2P_Cfg10_HW_Ver_Byte7_23 : 48|8@1+ (1,0) [0|255] ""  PC
 SG_ S2P_Cfg10_HW_Ver_Byte8_23 : 56|8@1+ (1,0) [0|255] ""  PC

BO_ 2417684056 S2P_Cfg10__24: 8 SBMU
 SG_ S2P_Cfg10_HW_Ver_Byte1_24 : 0|8@1+ (1,0) [0|255] ""  PC
 SG_ S2P_Cfg10_HW_Ver_Byte2_24 : 8|8@1+ (1,0) [0|255] ""  PC
 SG_ S2P_Cfg10_HW_Ver_Byte3_24 : 16|8@1+ (1,0) [0|255] ""  PC
 SG_ S2P_Cfg10_HW_Ver_Byte4_24 : 24|8@1+ (1,0) [0|255] ""  PC
 SG_ S2P_Cfg10_HW_Ver_Byte5_24 : 32|8@1+ (1,0) [0|255] ""  PC
 SG_ S2P_Cfg10_HW_Ver_Byte6_24 : 40|8@1+ (1,0) [0|255] ""  PC
 SG_ S2P_Cfg10_HW_Ver_Byte7_24 : 48|8@1+ (1,0) [0|255] ""  PC
 SG_ S2P_Cfg10_HW_Ver_Byte8_24 : 56|8@1+ (1,0) [0|255] ""  PC

BO_ 2417684057 S2P_Cfg10__25: 8 SBMU
 SG_ S2P_Cfg10_HW_Ver_Byte1_25 : 0|8@1+ (1,0) [0|255] ""  PC
 SG_ S2P_Cfg10_HW_Ver_Byte2_25 : 8|8@1+ (1,0) [0|255] ""  PC
 SG_ S2P_Cfg10_HW_Ver_Byte3_25 : 16|8@1+ (1,0) [0|255] ""  PC
 SG_ S2P_Cfg10_HW_Ver_Byte4_25 : 24|8@1+ (1,0) [0|255] ""  PC
 SG_ S2P_Cfg10_HW_Ver_Byte5_25 : 32|8@1+ (1,0) [0|255] ""  PC
 SG_ S2P_Cfg10_HW_Ver_Byte6_25 : 40|8@1+ (1,0) [0|255] ""  PC
 SG_ S2P_Cfg10_HW_Ver_Byte7_25 : 48|8@1+ (1,0) [0|255] ""  PC
 SG_ S2P_Cfg10_HW_Ver_Byte8_25 : 56|8@1+ (1,0) [0|255] ""  PC

BO_ 2417684058 S2P_Cfg10__26: 8 SBMU
 SG_ S2P_Cfg10_HW_Ver_Byte1_26 : 0|8@1+ (1,0) [0|255] ""  PC
 SG_ S2P_Cfg10_HW_Ver_Byte2_26 : 8|8@1+ (1,0) [0|255] ""  PC
 SG_ S2P_Cfg10_HW_Ver_Byte3_26 : 16|8@1+ (1,0) [0|255] ""  PC
 SG_ S2P_Cfg10_HW_Ver_Byte4_26 : 24|8@1+ (1,0) [0|255] ""  PC
 SG_ S2P_Cfg10_HW_Ver_Byte5_26 : 32|8@1+ (1,0) [0|255] ""  PC
 SG_ S2P_Cfg10_HW_Ver_Byte6_26 : 40|8@1+ (1,0) [0|255] ""  PC
 SG_ S2P_Cfg10_HW_Ver_Byte7_26 : 48|8@1+ (1,0) [0|255] ""  PC
 SG_ S2P_Cfg10_HW_Ver_Byte8_26 : 56|8@1+ (1,0) [0|255] ""  PC

BO_ 2417684059 S2P_Cfg10__27: 8 SBMU
 SG_ S2P_Cfg10_HW_Ver_Byte1_27 : 0|8@1+ (1,0) [0|255] ""  PC
 SG_ S2P_Cfg10_HW_Ver_Byte2_27 : 8|8@1+ (1,0) [0|255] ""  PC
 SG_ S2P_Cfg10_HW_Ver_Byte3_27 : 16|8@1+ (1,0) [0|255] ""  PC
 SG_ S2P_Cfg10_HW_Ver_Byte4_27 : 24|8@1+ (1,0) [0|255] ""  PC
 SG_ S2P_Cfg10_HW_Ver_Byte5_27 : 32|8@1+ (1,0) [0|255] ""  PC
 SG_ S2P_Cfg10_HW_Ver_Byte6_27 : 40|8@1+ (1,0) [0|255] ""  PC
 SG_ S2P_Cfg10_HW_Ver_Byte7_27 : 48|8@1+ (1,0) [0|255] ""  PC
 SG_ S2P_Cfg10_HW_Ver_Byte8_27 : 56|8@1+ (1,0) [0|255] ""  PC

BO_ 2417684060 S2P_Cfg10__28: 8 SBMU
 SG_ S2P_Cfg10_HW_Ver_Byte1_28 : 0|8@1+ (1,0) [0|255] ""  PC
 SG_ S2P_Cfg10_HW_Ver_Byte2_28 : 8|8@1+ (1,0) [0|255] ""  PC
 SG_ S2P_Cfg10_HW_Ver_Byte3_28 : 16|8@1+ (1,0) [0|255] ""  PC
 SG_ S2P_Cfg10_HW_Ver_Byte4_28 : 24|8@1+ (1,0) [0|255] ""  PC
 SG_ S2P_Cfg10_HW_Ver_Byte5_28 : 32|8@1+ (1,0) [0|255] ""  PC
 SG_ S2P_Cfg10_HW_Ver_Byte6_28 : 40|8@1+ (1,0) [0|255] ""  PC
 SG_ S2P_Cfg10_HW_Ver_Byte7_28 : 48|8@1+ (1,0) [0|255] ""  PC
 SG_ S2P_Cfg10_HW_Ver_Byte8_28 : 56|8@1+ (1,0) [0|255] ""  PC

BO_ 2417684061 S2P_Cfg10__29: 8 SBMU
 SG_ S2P_Cfg10_HW_Ver_Byte1_29 : 0|8@1+ (1,0) [0|255] ""  PC
 SG_ S2P_Cfg10_HW_Ver_Byte2_29 : 8|8@1+ (1,0) [0|255] ""  PC
 SG_ S2P_Cfg10_HW_Ver_Byte3_29 : 16|8@1+ (1,0) [0|255] ""  PC
 SG_ S2P_Cfg10_HW_Ver_Byte4_29 : 24|8@1+ (1,0) [0|255] ""  PC
 SG_ S2P_Cfg10_HW_Ver_Byte5_29 : 32|8@1+ (1,0) [0|255] ""  PC
 SG_ S2P_Cfg10_HW_Ver_Byte6_29 : 40|8@1+ (1,0) [0|255] ""  PC
 SG_ S2P_Cfg10_HW_Ver_Byte7_29 : 48|8@1+ (1,0) [0|255] ""  PC
 SG_ S2P_Cfg10_HW_Ver_Byte8_29 : 56|8@1+ (1,0) [0|255] ""  PC

BO_ 2417684062 S2P_Cfg10__30: 8 SBMU
 SG_ S2P_Cfg10_HW_Ver_Byte1_30 : 0|8@1+ (1,0) [0|255] ""  PC
 SG_ S2P_Cfg10_HW_Ver_Byte2_30 : 8|8@1+ (1,0) [0|255] ""  PC
 SG_ S2P_Cfg10_HW_Ver_Byte3_30 : 16|8@1+ (1,0) [0|255] ""  PC
 SG_ S2P_Cfg10_HW_Ver_Byte4_30 : 24|8@1+ (1,0) [0|255] ""  PC
 SG_ S2P_Cfg10_HW_Ver_Byte5_30 : 32|8@1+ (1,0) [0|255] ""  PC
 SG_ S2P_Cfg10_HW_Ver_Byte6_30 : 40|8@1+ (1,0) [0|255] ""  PC
 SG_ S2P_Cfg10_HW_Ver_Byte7_30 : 48|8@1+ (1,0) [0|255] ""  PC
 SG_ S2P_Cfg10_HW_Ver_Byte8_30 : 56|8@1+ (1,0) [0|255] ""  PC

BO_ 2417684063 S2P_Cfg10__31: 8 SBMU
 SG_ S2P_Cfg10_HW_Ver_Byte1_31 : 0|8@1+ (1,0) [0|255] ""  PC
 SG_ S2P_Cfg10_HW_Ver_Byte2_31 : 8|8@1+ (1,0) [0|255] ""  PC
 SG_ S2P_Cfg10_HW_Ver_Byte3_31 : 16|8@1+ (1,0) [0|255] ""  PC
 SG_ S2P_Cfg10_HW_Ver_Byte4_31 : 24|8@1+ (1,0) [0|255] ""  PC
 SG_ S2P_Cfg10_HW_Ver_Byte5_31 : 32|8@1+ (1,0) [0|255] ""  PC
 SG_ S2P_Cfg10_HW_Ver_Byte6_31 : 40|8@1+ (1,0) [0|255] ""  PC
 SG_ S2P_Cfg10_HW_Ver_Byte7_31 : 48|8@1+ (1,0) [0|255] ""  PC
 SG_ S2P_Cfg10_HW_Ver_Byte8_31 : 56|8@1+ (1,0) [0|255] ""  PC

BO_ 2417684064 S2P_Cfg10__32: 8 SBMU
 SG_ S2P_Cfg10_HW_Ver_Byte1_32 : 0|8@1+ (1,0) [0|255] ""  PC
 SG_ S2P_Cfg10_HW_Ver_Byte2_32 : 8|8@1+ (1,0) [0|255] ""  PC
 SG_ S2P_Cfg10_HW_Ver_Byte3_32 : 16|8@1+ (1,0) [0|255] ""  PC
 SG_ S2P_Cfg10_HW_Ver_Byte4_32 : 24|8@1+ (1,0) [0|255] ""  PC
 SG_ S2P_Cfg10_HW_Ver_Byte5_32 : 32|8@1+ (1,0) [0|255] ""  PC
 SG_ S2P_Cfg10_HW_Ver_Byte6_32 : 40|8@1+ (1,0) [0|255] ""  PC
 SG_ S2P_Cfg10_HW_Ver_Byte7_32 : 48|8@1+ (1,0) [0|255] ""  PC
 SG_ S2P_Cfg10_HW_Ver_Byte8_32 : 56|8@1+ (1,0) [0|255] ""  PC

BO_ 2417684065 S2P_Cfg10__33: 8 SBMU
 SG_ S2P_Cfg10_HW_Ver_Byte1_33 : 0|8@1+ (1,0) [0|255] ""  PC
 SG_ S2P_Cfg10_HW_Ver_Byte2_33 : 8|8@1+ (1,0) [0|255] ""  PC
 SG_ S2P_Cfg10_HW_Ver_Byte3_33 : 16|8@1+ (1,0) [0|255] ""  PC
 SG_ S2P_Cfg10_HW_Ver_Byte4_33 : 24|8@1+ (1,0) [0|255] ""  PC
 SG_ S2P_Cfg10_HW_Ver_Byte5_33 : 32|8@1+ (1,0) [0|255] ""  PC
 SG_ S2P_Cfg10_HW_Ver_Byte6_33 : 40|8@1+ (1,0) [0|255] ""  PC
 SG_ S2P_Cfg10_HW_Ver_Byte7_33 : 48|8@1+ (1,0) [0|255] ""  PC
 SG_ S2P_Cfg10_HW_Ver_Byte8_33 : 56|8@1+ (1,0) [0|255] ""  PC

BO_ 2417684066 S2P_Cfg10__34: 8 SBMU
 SG_ S2P_Cfg10_HW_Ver_Byte1_34 : 0|8@1+ (1,0) [0|255] ""  PC
 SG_ S2P_Cfg10_HW_Ver_Byte2_34 : 8|8@1+ (1,0) [0|255] ""  PC
 SG_ S2P_Cfg10_HW_Ver_Byte3_34 : 16|8@1+ (1,0) [0|255] ""  PC
 SG_ S2P_Cfg10_HW_Ver_Byte4_34 : 24|8@1+ (1,0) [0|255] ""  PC
 SG_ S2P_Cfg10_HW_Ver_Byte5_34 : 32|8@1+ (1,0) [0|255] ""  PC
 SG_ S2P_Cfg10_HW_Ver_Byte6_34 : 40|8@1+ (1,0) [0|255] ""  PC
 SG_ S2P_Cfg10_HW_Ver_Byte7_34 : 48|8@1+ (1,0) [0|255] ""  PC
 SG_ S2P_Cfg10_HW_Ver_Byte8_34 : 56|8@1+ (1,0) [0|255] ""  PC

BO_ 2417684067 S2P_Cfg10__35: 8 SBMU
 SG_ S2P_Cfg10_HW_Ver_Byte1_35 : 0|8@1+ (1,0) [0|255] ""  PC
 SG_ S2P_Cfg10_HW_Ver_Byte2_35 : 8|8@1+ (1,0) [0|255] ""  PC
 SG_ S2P_Cfg10_HW_Ver_Byte3_35 : 16|8@1+ (1,0) [0|255] ""  PC
 SG_ S2P_Cfg10_HW_Ver_Byte4_35 : 24|8@1+ (1,0) [0|255] ""  PC
 SG_ S2P_Cfg10_HW_Ver_Byte5_35 : 32|8@1+ (1,0) [0|255] ""  PC
 SG_ S2P_Cfg10_HW_Ver_Byte6_35 : 40|8@1+ (1,0) [0|255] ""  PC
 SG_ S2P_Cfg10_HW_Ver_Byte7_35 : 48|8@1+ (1,0) [0|255] ""  PC
 SG_ S2P_Cfg10_HW_Ver_Byte8_35 : 56|8@1+ (1,0) [0|255] ""  PC

BO_ 2417684068 S2P_Cfg10__36: 8 SBMU
 SG_ S2P_Cfg10_HW_Ver_Byte1_36 : 0|8@1+ (1,0) [0|255] ""  PC
 SG_ S2P_Cfg10_HW_Ver_Byte2_36 : 8|8@1+ (1,0) [0|255] ""  PC
 SG_ S2P_Cfg10_HW_Ver_Byte3_36 : 16|8@1+ (1,0) [0|255] ""  PC
 SG_ S2P_Cfg10_HW_Ver_Byte4_36 : 24|8@1+ (1,0) [0|255] ""  PC
 SG_ S2P_Cfg10_HW_Ver_Byte5_36 : 32|8@1+ (1,0) [0|255] ""  PC
 SG_ S2P_Cfg10_HW_Ver_Byte6_36 : 40|8@1+ (1,0) [0|255] ""  PC
 SG_ S2P_Cfg10_HW_Ver_Byte7_36 : 48|8@1+ (1,0) [0|255] ""  PC
 SG_ S2P_Cfg10_HW_Ver_Byte8_36 : 56|8@1+ (1,0) [0|255] ""  PC

BO_ 2417684069 S2P_Cfg10__37: 8 SBMU
 SG_ S2P_Cfg10_HW_Ver_Byte1_37 : 0|8@1+ (1,0) [0|255] ""  PC
 SG_ S2P_Cfg10_HW_Ver_Byte2_37 : 8|8@1+ (1,0) [0|255] ""  PC
 SG_ S2P_Cfg10_HW_Ver_Byte3_37 : 16|8@1+ (1,0) [0|255] ""  PC
 SG_ S2P_Cfg10_HW_Ver_Byte4_37 : 24|8@1+ (1,0) [0|255] ""  PC
 SG_ S2P_Cfg10_HW_Ver_Byte5_37 : 32|8@1+ (1,0) [0|255] ""  PC
 SG_ S2P_Cfg10_HW_Ver_Byte6_37 : 40|8@1+ (1,0) [0|255] ""  PC
 SG_ S2P_Cfg10_HW_Ver_Byte7_37 : 48|8@1+ (1,0) [0|255] ""  PC
 SG_ S2P_Cfg10_HW_Ver_Byte8_37 : 56|8@1+ (1,0) [0|255] ""  PC

BO_ 2417684070 S2P_Cfg10__38: 8 SBMU
 SG_ S2P_Cfg10_HW_Ver_Byte1_38 : 0|8@1+ (1,0) [0|255] ""  PC
 SG_ S2P_Cfg10_HW_Ver_Byte2_38 : 8|8@1+ (1,0) [0|255] ""  PC
 SG_ S2P_Cfg10_HW_Ver_Byte3_38 : 16|8@1+ (1,0) [0|255] ""  PC
 SG_ S2P_Cfg10_HW_Ver_Byte4_38 : 24|8@1+ (1,0) [0|255] ""  PC
 SG_ S2P_Cfg10_HW_Ver_Byte5_38 : 32|8@1+ (1,0) [0|255] ""  PC
 SG_ S2P_Cfg10_HW_Ver_Byte6_38 : 40|8@1+ (1,0) [0|255] ""  PC
 SG_ S2P_Cfg10_HW_Ver_Byte7_38 : 48|8@1+ (1,0) [0|255] ""  PC
 SG_ S2P_Cfg10_HW_Ver_Byte8_38 : 56|8@1+ (1,0) [0|255] ""  PC

BO_ 2417684071 S2P_Cfg10__39: 8 SBMU
 SG_ S2P_Cfg10_HW_Ver_Byte1_39 : 0|8@1+ (1,0) [0|255] ""  PC
 SG_ S2P_Cfg10_HW_Ver_Byte2_39 : 8|8@1+ (1,0) [0|255] ""  PC
 SG_ S2P_Cfg10_HW_Ver_Byte3_39 : 16|8@1+ (1,0) [0|255] ""  PC
 SG_ S2P_Cfg10_HW_Ver_Byte4_39 : 24|8@1+ (1,0) [0|255] ""  PC
 SG_ S2P_Cfg10_HW_Ver_Byte5_39 : 32|8@1+ (1,0) [0|255] ""  PC
 SG_ S2P_Cfg10_HW_Ver_Byte6_39 : 40|8@1+ (1,0) [0|255] ""  PC
 SG_ S2P_Cfg10_HW_Ver_Byte7_39 : 48|8@1+ (1,0) [0|255] ""  PC
 SG_ S2P_Cfg10_HW_Ver_Byte8_39 : 56|8@1+ (1,0) [0|255] ""  PC

BO_ 2417684072 S2P_Cfg10__40: 8 SBMU
 SG_ S2P_Cfg10_HW_Ver_Byte1_40 : 0|8@1+ (1,0) [0|255] ""  PC
 SG_ S2P_Cfg10_HW_Ver_Byte2_40 : 8|8@1+ (1,0) [0|255] ""  PC
 SG_ S2P_Cfg10_HW_Ver_Byte3_40 : 16|8@1+ (1,0) [0|255] ""  PC
 SG_ S2P_Cfg10_HW_Ver_Byte4_40 : 24|8@1+ (1,0) [0|255] ""  PC
 SG_ S2P_Cfg10_HW_Ver_Byte5_40 : 32|8@1+ (1,0) [0|255] ""  PC
 SG_ S2P_Cfg10_HW_Ver_Byte6_40 : 40|8@1+ (1,0) [0|255] ""  PC
 SG_ S2P_Cfg10_HW_Ver_Byte7_40 : 48|8@1+ (1,0) [0|255] ""  PC
 SG_ S2P_Cfg10_HW_Ver_Byte8_40 : 56|8@1+ (1,0) [0|255] ""  PC

BO_ 2417684073 S2P_Cfg10__41: 8 SBMU
 SG_ S2P_Cfg10_HW_Ver_Byte1_41 : 0|8@1+ (1,0) [0|255] ""  PC
 SG_ S2P_Cfg10_HW_Ver_Byte2_41 : 8|8@1+ (1,0) [0|255] ""  PC
 SG_ S2P_Cfg10_HW_Ver_Byte3_41 : 16|8@1+ (1,0) [0|255] ""  PC
 SG_ S2P_Cfg10_HW_Ver_Byte4_41 : 24|8@1+ (1,0) [0|255] ""  PC
 SG_ S2P_Cfg10_HW_Ver_Byte5_41 : 32|8@1+ (1,0) [0|255] ""  PC
 SG_ S2P_Cfg10_HW_Ver_Byte6_41 : 40|8@1+ (1,0) [0|255] ""  PC
 SG_ S2P_Cfg10_HW_Ver_Byte7_41 : 48|8@1+ (1,0) [0|255] ""  PC
 SG_ S2P_Cfg10_HW_Ver_Byte8_41 : 56|8@1+ (1,0) [0|255] ""  PC

BO_ 2417684074 S2P_Cfg10__42: 8 SBMU
 SG_ S2P_Cfg10_HW_Ver_Byte1_42 : 0|8@1+ (1,0) [0|255] ""  PC
 SG_ S2P_Cfg10_HW_Ver_Byte2_42 : 8|8@1+ (1,0) [0|255] ""  PC
 SG_ S2P_Cfg10_HW_Ver_Byte3_42 : 16|8@1+ (1,0) [0|255] ""  PC
 SG_ S2P_Cfg10_HW_Ver_Byte4_42 : 24|8@1+ (1,0) [0|255] ""  PC
 SG_ S2P_Cfg10_HW_Ver_Byte5_42 : 32|8@1+ (1,0) [0|255] ""  PC
 SG_ S2P_Cfg10_HW_Ver_Byte6_42 : 40|8@1+ (1,0) [0|255] ""  PC
 SG_ S2P_Cfg10_HW_Ver_Byte7_42 : 48|8@1+ (1,0) [0|255] ""  PC
 SG_ S2P_Cfg10_HW_Ver_Byte8_42 : 56|8@1+ (1,0) [0|255] ""  PC

BO_ 2417684075 S2P_Cfg10__43: 8 SBMU
 SG_ S2P_Cfg10_HW_Ver_Byte1_43 : 0|8@1+ (1,0) [0|255] ""  PC
 SG_ S2P_Cfg10_HW_Ver_Byte2_43 : 8|8@1+ (1,0) [0|255] ""  PC
 SG_ S2P_Cfg10_HW_Ver_Byte3_43 : 16|8@1+ (1,0) [0|255] ""  PC
 SG_ S2P_Cfg10_HW_Ver_Byte4_43 : 24|8@1+ (1,0) [0|255] ""  PC
 SG_ S2P_Cfg10_HW_Ver_Byte5_43 : 32|8@1+ (1,0) [0|255] ""  PC
 SG_ S2P_Cfg10_HW_Ver_Byte6_43 : 40|8@1+ (1,0) [0|255] ""  PC
 SG_ S2P_Cfg10_HW_Ver_Byte7_43 : 48|8@1+ (1,0) [0|255] ""  PC
 SG_ S2P_Cfg10_HW_Ver_Byte8_43 : 56|8@1+ (1,0) [0|255] ""  PC

BO_ 2417684076 S2P_Cfg10__44: 8 SBMU
 SG_ S2P_Cfg10_HW_Ver_Byte1_44 : 0|8@1+ (1,0) [0|255] ""  PC
 SG_ S2P_Cfg10_HW_Ver_Byte2_44 : 8|8@1+ (1,0) [0|255] ""  PC
 SG_ S2P_Cfg10_HW_Ver_Byte3_44 : 16|8@1+ (1,0) [0|255] ""  PC
 SG_ S2P_Cfg10_HW_Ver_Byte4_44 : 24|8@1+ (1,0) [0|255] ""  PC
 SG_ S2P_Cfg10_HW_Ver_Byte5_44 : 32|8@1+ (1,0) [0|255] ""  PC
 SG_ S2P_Cfg10_HW_Ver_Byte6_44 : 40|8@1+ (1,0) [0|255] ""  PC
 SG_ S2P_Cfg10_HW_Ver_Byte7_44 : 48|8@1+ (1,0) [0|255] ""  PC
 SG_ S2P_Cfg10_HW_Ver_Byte8_44 : 56|8@1+ (1,0) [0|255] ""  PC

BO_ 2417684077 S2P_Cfg10__45: 8 SBMU
 SG_ S2P_Cfg10_HW_Ver_Byte1_45 : 0|8@1+ (1,0) [0|255] ""  PC
 SG_ S2P_Cfg10_HW_Ver_Byte2_45 : 8|8@1+ (1,0) [0|255] ""  PC
 SG_ S2P_Cfg10_HW_Ver_Byte3_45 : 16|8@1+ (1,0) [0|255] ""  PC
 SG_ S2P_Cfg10_HW_Ver_Byte4_45 : 24|8@1+ (1,0) [0|255] ""  PC
 SG_ S2P_Cfg10_HW_Ver_Byte5_45 : 32|8@1+ (1,0) [0|255] ""  PC
 SG_ S2P_Cfg10_HW_Ver_Byte6_45 : 40|8@1+ (1,0) [0|255] ""  PC
 SG_ S2P_Cfg10_HW_Ver_Byte7_45 : 48|8@1+ (1,0) [0|255] ""  PC
 SG_ S2P_Cfg10_HW_Ver_Byte8_45 : 56|8@1+ (1,0) [0|255] ""  PC

BO_ 2417684078 S2P_Cfg10__46: 8 SBMU
 SG_ S2P_Cfg10_HW_Ver_Byte1_46 : 0|8@1+ (1,0) [0|255] ""  PC
 SG_ S2P_Cfg10_HW_Ver_Byte2_46 : 8|8@1+ (1,0) [0|255] ""  PC
 SG_ S2P_Cfg10_HW_Ver_Byte3_46 : 16|8@1+ (1,0) [0|255] ""  PC
 SG_ S2P_Cfg10_HW_Ver_Byte4_46 : 24|8@1+ (1,0) [0|255] ""  PC
 SG_ S2P_Cfg10_HW_Ver_Byte5_46 : 32|8@1+ (1,0) [0|255] ""  PC
 SG_ S2P_Cfg10_HW_Ver_Byte6_46 : 40|8@1+ (1,0) [0|255] ""  PC
 SG_ S2P_Cfg10_HW_Ver_Byte7_46 : 48|8@1+ (1,0) [0|255] ""  PC
 SG_ S2P_Cfg10_HW_Ver_Byte8_46 : 56|8@1+ (1,0) [0|255] ""  PC

BO_ 2417684079 S2P_Cfg10__47: 8 SBMU
 SG_ S2P_Cfg10_HW_Ver_Byte1_47 : 0|8@1+ (1,0) [0|255] ""  PC
 SG_ S2P_Cfg10_HW_Ver_Byte2_47 : 8|8@1+ (1,0) [0|255] ""  PC
 SG_ S2P_Cfg10_HW_Ver_Byte3_47 : 16|8@1+ (1,0) [0|255] ""  PC
 SG_ S2P_Cfg10_HW_Ver_Byte4_47 : 24|8@1+ (1,0) [0|255] ""  PC
 SG_ S2P_Cfg10_HW_Ver_Byte5_47 : 32|8@1+ (1,0) [0|255] ""  PC
 SG_ S2P_Cfg10_HW_Ver_Byte6_47 : 40|8@1+ (1,0) [0|255] ""  PC
 SG_ S2P_Cfg10_HW_Ver_Byte7_47 : 48|8@1+ (1,0) [0|255] ""  PC
 SG_ S2P_Cfg10_HW_Ver_Byte8_47 : 56|8@1+ (1,0) [0|255] ""  PC

BO_ 2417684080 S2P_Cfg10__48: 8 SBMU
 SG_ S2P_Cfg10_HW_Ver_Byte1_48 : 0|8@1+ (1,0) [0|255] ""  PC
 SG_ S2P_Cfg10_HW_Ver_Byte2_48 : 8|8@1+ (1,0) [0|255] ""  PC
 SG_ S2P_Cfg10_HW_Ver_Byte3_48 : 16|8@1+ (1,0) [0|255] ""  PC
 SG_ S2P_Cfg10_HW_Ver_Byte4_48 : 24|8@1+ (1,0) [0|255] ""  PC
 SG_ S2P_Cfg10_HW_Ver_Byte5_48 : 32|8@1+ (1,0) [0|255] ""  PC
 SG_ S2P_Cfg10_HW_Ver_Byte6_48 : 40|8@1+ (1,0) [0|255] ""  PC
 SG_ S2P_Cfg10_HW_Ver_Byte7_48 : 48|8@1+ (1,0) [0|255] ""  PC
 SG_ S2P_Cfg10_HW_Ver_Byte8_48 : 56|8@1+ (1,0) [0|255] ""  PC

BO_ 2417684081 S2P_Cfg10__49: 8 SBMU
 SG_ S2P_Cfg10_HW_Ver_Byte1_49 : 0|8@1+ (1,0) [0|255] ""  PC
 SG_ S2P_Cfg10_HW_Ver_Byte2_49 : 8|8@1+ (1,0) [0|255] ""  PC
 SG_ S2P_Cfg10_HW_Ver_Byte3_49 : 16|8@1+ (1,0) [0|255] ""  PC
 SG_ S2P_Cfg10_HW_Ver_Byte4_49 : 24|8@1+ (1,0) [0|255] ""  PC
 SG_ S2P_Cfg10_HW_Ver_Byte5_49 : 32|8@1+ (1,0) [0|255] ""  PC
 SG_ S2P_Cfg10_HW_Ver_Byte6_49 : 40|8@1+ (1,0) [0|255] ""  PC
 SG_ S2P_Cfg10_HW_Ver_Byte7_49 : 48|8@1+ (1,0) [0|255] ""  PC
 SG_ S2P_Cfg10_HW_Ver_Byte8_49 : 56|8@1+ (1,0) [0|255] ""  PC

BO_ 2417684082 S2P_Cfg10__50: 8 SBMU
 SG_ S2P_Cfg10_HW_Ver_Byte1_50 : 0|8@1+ (1,0) [0|255] ""  PC
 SG_ S2P_Cfg10_HW_Ver_Byte2_50 : 8|8@1+ (1,0) [0|255] ""  PC
 SG_ S2P_Cfg10_HW_Ver_Byte3_50 : 16|8@1+ (1,0) [0|255] ""  PC
 SG_ S2P_Cfg10_HW_Ver_Byte4_50 : 24|8@1+ (1,0) [0|255] ""  PC
 SG_ S2P_Cfg10_HW_Ver_Byte5_50 : 32|8@1+ (1,0) [0|255] ""  PC
 SG_ S2P_Cfg10_HW_Ver_Byte6_50 : 40|8@1+ (1,0) [0|255] ""  PC
 SG_ S2P_Cfg10_HW_Ver_Byte7_50 : 48|8@1+ (1,0) [0|255] ""  PC
 SG_ S2P_Cfg10_HW_Ver_Byte8_50 : 56|8@1+ (1,0) [0|255] ""  PC

BO_ 2417684083 S2P_Cfg10__51: 8 SBMU
 SG_ S2P_Cfg10_HW_Ver_Byte1_51 : 0|8@1+ (1,0) [0|255] ""  PC
 SG_ S2P_Cfg10_HW_Ver_Byte2_51 : 8|8@1+ (1,0) [0|255] ""  PC
 SG_ S2P_Cfg10_HW_Ver_Byte3_51 : 16|8@1+ (1,0) [0|255] ""  PC
 SG_ S2P_Cfg10_HW_Ver_Byte4_51 : 24|8@1+ (1,0) [0|255] ""  PC
 SG_ S2P_Cfg10_HW_Ver_Byte5_51 : 32|8@1+ (1,0) [0|255] ""  PC
 SG_ S2P_Cfg10_HW_Ver_Byte6_51 : 40|8@1+ (1,0) [0|255] ""  PC
 SG_ S2P_Cfg10_HW_Ver_Byte7_51 : 48|8@1+ (1,0) [0|255] ""  PC
 SG_ S2P_Cfg10_HW_Ver_Byte8_51 : 56|8@1+ (1,0) [0|255] ""  PC

BO_ 2417684084 S2P_Cfg10__52: 8 SBMU
 SG_ S2P_Cfg10_HW_Ver_Byte1_52 : 0|8@1+ (1,0) [0|255] ""  PC
 SG_ S2P_Cfg10_HW_Ver_Byte2_52 : 8|8@1+ (1,0) [0|255] ""  PC
 SG_ S2P_Cfg10_HW_Ver_Byte3_52 : 16|8@1+ (1,0) [0|255] ""  PC
 SG_ S2P_Cfg10_HW_Ver_Byte4_52 : 24|8@1+ (1,0) [0|255] ""  PC
 SG_ S2P_Cfg10_HW_Ver_Byte5_52 : 32|8@1+ (1,0) [0|255] ""  PC
 SG_ S2P_Cfg10_HW_Ver_Byte6_52 : 40|8@1+ (1,0) [0|255] ""  PC
 SG_ S2P_Cfg10_HW_Ver_Byte7_52 : 48|8@1+ (1,0) [0|255] ""  PC
 SG_ S2P_Cfg10_HW_Ver_Byte8_52 : 56|8@1+ (1,0) [0|255] ""  PC

BO_ 2417684085 S2P_Cfg10__53: 8 SBMU
 SG_ S2P_Cfg10_HW_Ver_Byte1_53 : 0|8@1+ (1,0) [0|255] ""  PC
 SG_ S2P_Cfg10_HW_Ver_Byte2_53 : 8|8@1+ (1,0) [0|255] ""  PC
 SG_ S2P_Cfg10_HW_Ver_Byte3_53 : 16|8@1+ (1,0) [0|255] ""  PC
 SG_ S2P_Cfg10_HW_Ver_Byte4_53 : 24|8@1+ (1,0) [0|255] ""  PC
 SG_ S2P_Cfg10_HW_Ver_Byte5_53 : 32|8@1+ (1,0) [0|255] ""  PC
 SG_ S2P_Cfg10_HW_Ver_Byte6_53 : 40|8@1+ (1,0) [0|255] ""  PC
 SG_ S2P_Cfg10_HW_Ver_Byte7_53 : 48|8@1+ (1,0) [0|255] ""  PC
 SG_ S2P_Cfg10_HW_Ver_Byte8_53 : 56|8@1+ (1,0) [0|255] ""  PC

BO_ 2417684086 S2P_Cfg10__54: 8 SBMU
 SG_ S2P_Cfg10_HW_Ver_Byte1_54 : 0|8@1+ (1,0) [0|255] ""  PC
 SG_ S2P_Cfg10_HW_Ver_Byte2_54 : 8|8@1+ (1,0) [0|255] ""  PC
 SG_ S2P_Cfg10_HW_Ver_Byte3_54 : 16|8@1+ (1,0) [0|255] ""  PC
 SG_ S2P_Cfg10_HW_Ver_Byte4_54 : 24|8@1+ (1,0) [0|255] ""  PC
 SG_ S2P_Cfg10_HW_Ver_Byte5_54 : 32|8@1+ (1,0) [0|255] ""  PC
 SG_ S2P_Cfg10_HW_Ver_Byte6_54 : 40|8@1+ (1,0) [0|255] ""  PC
 SG_ S2P_Cfg10_HW_Ver_Byte7_54 : 48|8@1+ (1,0) [0|255] ""  PC
 SG_ S2P_Cfg10_HW_Ver_Byte8_54 : 56|8@1+ (1,0) [0|255] ""  PC

BO_ 2417684087 S2P_Cfg10__55: 8 SBMU
 SG_ S2P_Cfg10_HW_Ver_Byte1_55 : 0|8@1+ (1,0) [0|255] ""  PC
 SG_ S2P_Cfg10_HW_Ver_Byte2_55 : 8|8@1+ (1,0) [0|255] ""  PC
 SG_ S2P_Cfg10_HW_Ver_Byte3_55 : 16|8@1+ (1,0) [0|255] ""  PC
 SG_ S2P_Cfg10_HW_Ver_Byte4_55 : 24|8@1+ (1,0) [0|255] ""  PC
 SG_ S2P_Cfg10_HW_Ver_Byte5_55 : 32|8@1+ (1,0) [0|255] ""  PC
 SG_ S2P_Cfg10_HW_Ver_Byte6_55 : 40|8@1+ (1,0) [0|255] ""  PC
 SG_ S2P_Cfg10_HW_Ver_Byte7_55 : 48|8@1+ (1,0) [0|255] ""  PC
 SG_ S2P_Cfg10_HW_Ver_Byte8_55 : 56|8@1+ (1,0) [0|255] ""  PC

BO_ 2417684088 S2P_Cfg10__56: 8 SBMU
 SG_ S2P_Cfg10_HW_Ver_Byte1_56 : 0|8@1+ (1,0) [0|255] ""  PC
 SG_ S2P_Cfg10_HW_Ver_Byte2_56 : 8|8@1+ (1,0) [0|255] ""  PC
 SG_ S2P_Cfg10_HW_Ver_Byte3_56 : 16|8@1+ (1,0) [0|255] ""  PC
 SG_ S2P_Cfg10_HW_Ver_Byte4_56 : 24|8@1+ (1,0) [0|255] ""  PC
 SG_ S2P_Cfg10_HW_Ver_Byte5_56 : 32|8@1+ (1,0) [0|255] ""  PC
 SG_ S2P_Cfg10_HW_Ver_Byte6_56 : 40|8@1+ (1,0) [0|255] ""  PC
 SG_ S2P_Cfg10_HW_Ver_Byte7_56 : 48|8@1+ (1,0) [0|255] ""  PC
 SG_ S2P_Cfg10_HW_Ver_Byte8_56 : 56|8@1+ (1,0) [0|255] ""  PC

BO_ 2417684089 S2P_Cfg10__57: 8 SBMU
 SG_ S2P_Cfg10_HW_Ver_Byte1_57 : 0|8@1+ (1,0) [0|255] ""  PC
 SG_ S2P_Cfg10_HW_Ver_Byte2_57 : 8|8@1+ (1,0) [0|255] ""  PC
 SG_ S2P_Cfg10_HW_Ver_Byte3_57 : 16|8@1+ (1,0) [0|255] ""  PC
 SG_ S2P_Cfg10_HW_Ver_Byte4_57 : 24|8@1+ (1,0) [0|255] ""  PC
 SG_ S2P_Cfg10_HW_Ver_Byte5_57 : 32|8@1+ (1,0) [0|255] ""  PC
 SG_ S2P_Cfg10_HW_Ver_Byte6_57 : 40|8@1+ (1,0) [0|255] ""  PC
 SG_ S2P_Cfg10_HW_Ver_Byte7_57 : 48|8@1+ (1,0) [0|255] ""  PC
 SG_ S2P_Cfg10_HW_Ver_Byte8_57 : 56|8@1+ (1,0) [0|255] ""  PC

BO_ 2417684090 S2P_Cfg10__58: 8 SBMU
 SG_ S2P_Cfg10_HW_Ver_Byte1_58 : 0|8@1+ (1,0) [0|255] ""  PC
 SG_ S2P_Cfg10_HW_Ver_Byte2_58 : 8|8@1+ (1,0) [0|255] ""  PC
 SG_ S2P_Cfg10_HW_Ver_Byte3_58 : 16|8@1+ (1,0) [0|255] ""  PC
 SG_ S2P_Cfg10_HW_Ver_Byte4_58 : 24|8@1+ (1,0) [0|255] ""  PC
 SG_ S2P_Cfg10_HW_Ver_Byte5_58 : 32|8@1+ (1,0) [0|255] ""  PC
 SG_ S2P_Cfg10_HW_Ver_Byte6_58 : 40|8@1+ (1,0) [0|255] ""  PC
 SG_ S2P_Cfg10_HW_Ver_Byte7_58 : 48|8@1+ (1,0) [0|255] ""  PC
 SG_ S2P_Cfg10_HW_Ver_Byte8_58 : 56|8@1+ (1,0) [0|255] ""  PC

BO_ 2417684091 S2P_Cfg10__59: 8 SBMU
 SG_ S2P_Cfg10_HW_Ver_Byte1_59 : 0|8@1+ (1,0) [0|255] ""  PC
 SG_ S2P_Cfg10_HW_Ver_Byte2_59 : 8|8@1+ (1,0) [0|255] ""  PC
 SG_ S2P_Cfg10_HW_Ver_Byte3_59 : 16|8@1+ (1,0) [0|255] ""  PC
 SG_ S2P_Cfg10_HW_Ver_Byte4_59 : 24|8@1+ (1,0) [0|255] ""  PC
 SG_ S2P_Cfg10_HW_Ver_Byte5_59 : 32|8@1+ (1,0) [0|255] ""  PC
 SG_ S2P_Cfg10_HW_Ver_Byte6_59 : 40|8@1+ (1,0) [0|255] ""  PC
 SG_ S2P_Cfg10_HW_Ver_Byte7_59 : 48|8@1+ (1,0) [0|255] ""  PC
 SG_ S2P_Cfg10_HW_Ver_Byte8_59 : 56|8@1+ (1,0) [0|255] ""  PC

BO_ 2417684092 S2P_Cfg10__60: 8 SBMU
 SG_ S2P_Cfg10_HW_Ver_Byte1_60 : 0|8@1+ (1,0) [0|255] ""  PC
 SG_ S2P_Cfg10_HW_Ver_Byte2_60 : 8|8@1+ (1,0) [0|255] ""  PC
 SG_ S2P_Cfg10_HW_Ver_Byte3_60 : 16|8@1+ (1,0) [0|255] ""  PC
 SG_ S2P_Cfg10_HW_Ver_Byte4_60 : 24|8@1+ (1,0) [0|255] ""  PC
 SG_ S2P_Cfg10_HW_Ver_Byte5_60 : 32|8@1+ (1,0) [0|255] ""  PC
 SG_ S2P_Cfg10_HW_Ver_Byte6_60 : 40|8@1+ (1,0) [0|255] ""  PC
 SG_ S2P_Cfg10_HW_Ver_Byte7_60 : 48|8@1+ (1,0) [0|255] ""  PC
 SG_ S2P_Cfg10_HW_Ver_Byte8_60 : 56|8@1+ (1,0) [0|255] ""  PC

BO_ 2417684093 S2P_Cfg10__61: 8 SBMU
 SG_ S2P_Cfg10_HW_Ver_Byte1_61 : 0|8@1+ (1,0) [0|255] ""  PC
 SG_ S2P_Cfg10_HW_Ver_Byte2_61 : 8|8@1+ (1,0) [0|255] ""  PC
 SG_ S2P_Cfg10_HW_Ver_Byte3_61 : 16|8@1+ (1,0) [0|255] ""  PC
 SG_ S2P_Cfg10_HW_Ver_Byte4_61 : 24|8@1+ (1,0) [0|255] ""  PC
 SG_ S2P_Cfg10_HW_Ver_Byte5_61 : 32|8@1+ (1,0) [0|255] ""  PC
 SG_ S2P_Cfg10_HW_Ver_Byte6_61 : 40|8@1+ (1,0) [0|255] ""  PC
 SG_ S2P_Cfg10_HW_Ver_Byte7_61 : 48|8@1+ (1,0) [0|255] ""  PC
 SG_ S2P_Cfg10_HW_Ver_Byte8_61 : 56|8@1+ (1,0) [0|255] ""  PC

BO_ 2417684094 S2P_Cfg10__62: 8 SBMU
 SG_ S2P_Cfg10_HW_Ver_Byte1_62 : 0|8@1+ (1,0) [0|255] ""  PC
 SG_ S2P_Cfg10_HW_Ver_Byte2_62 : 8|8@1+ (1,0) [0|255] ""  PC
 SG_ S2P_Cfg10_HW_Ver_Byte3_62 : 16|8@1+ (1,0) [0|255] ""  PC
 SG_ S2P_Cfg10_HW_Ver_Byte4_62 : 24|8@1+ (1,0) [0|255] ""  PC
 SG_ S2P_Cfg10_HW_Ver_Byte5_62 : 32|8@1+ (1,0) [0|255] ""  PC
 SG_ S2P_Cfg10_HW_Ver_Byte6_62 : 40|8@1+ (1,0) [0|255] ""  PC
 SG_ S2P_Cfg10_HW_Ver_Byte7_62 : 48|8@1+ (1,0) [0|255] ""  PC
 SG_ S2P_Cfg10_HW_Ver_Byte8_62 : 56|8@1+ (1,0) [0|255] ""  PC

BO_ 2417684095 S2P_Cfg10__63: 8 SBMU
 SG_ S2P_Cfg10_HW_Ver_Byte1_63 : 0|8@1+ (1,0) [0|255] ""  PC
 SG_ S2P_Cfg10_HW_Ver_Byte2_63 : 8|8@1+ (1,0) [0|255] ""  PC
 SG_ S2P_Cfg10_HW_Ver_Byte3_63 : 16|8@1+ (1,0) [0|255] ""  PC
 SG_ S2P_Cfg10_HW_Ver_Byte4_63 : 24|8@1+ (1,0) [0|255] ""  PC
 SG_ S2P_Cfg10_HW_Ver_Byte5_63 : 32|8@1+ (1,0) [0|255] ""  PC
 SG_ S2P_Cfg10_HW_Ver_Byte6_63 : 40|8@1+ (1,0) [0|255] ""  PC
 SG_ S2P_Cfg10_HW_Ver_Byte7_63 : 48|8@1+ (1,0) [0|255] ""  PC
 SG_ S2P_Cfg10_HW_Ver_Byte8_63 : 56|8@1+ (1,0) [0|255] ""  PC

BO_ 2417749569 S2P_Cfg11__01: 8 SBMU
 SG_ S2P_Cfg11_HW_Ver_Byte9_01 : 0|8@1+ (1,0) [0|255] ""  PC
 SG_ S2P_Cfg11_HW_Ver_Byte10_01 : 8|8@1+ (1,0) [0|255] ""  PC
 SG_ S2P_Cfg11_HW_Ver_Byte11_01 : 16|8@1+ (1,0) [0|255] ""  PC
 SG_ S2P_Cfg11_HW_Ver_Byte12_01 : 24|8@1+ (1,0) [0|255] ""  PC
 SG_ S2P_Cfg11_HW_Ver_Byte13_01 : 32|8@1+ (1,0) [0|255] ""  PC
 SG_ S2P_Cfg11_HW_Ver_Byte14_01 : 40|8@1+ (1,0) [0|255] ""  PC
 SG_ S2P_Cfg11_HW_Ver_Byte15_01 : 48|8@1+ (1,0) [0|255] ""  PC
 SG_ S2P_Cfg11_HW_Ver_Byte16_01 : 56|8@1+ (1,0) [0|255] ""  PC

BO_ 2417749570 S2P_Cfg11__02: 8 SBMU
 SG_ S2P_Cfg11_HW_Ver_Byte9_02 : 0|8@1+ (1,0) [0|255] ""  PC
 SG_ S2P_Cfg11_HW_Ver_Byte10_02 : 8|8@1+ (1,0) [0|255] ""  PC
 SG_ S2P_Cfg11_HW_Ver_Byte11_02 : 16|8@1+ (1,0) [0|255] ""  PC
 SG_ S2P_Cfg11_HW_Ver_Byte12_02 : 24|8@1+ (1,0) [0|255] ""  PC
 SG_ S2P_Cfg11_HW_Ver_Byte13_02 : 32|8@1+ (1,0) [0|255] ""  PC
 SG_ S2P_Cfg11_HW_Ver_Byte14_02 : 40|8@1+ (1,0) [0|255] ""  PC
 SG_ S2P_Cfg11_HW_Ver_Byte15_02 : 48|8@1+ (1,0) [0|255] ""  PC
 SG_ S2P_Cfg11_HW_Ver_Byte16_02 : 56|8@1+ (1,0) [0|255] ""  PC

BO_ 2417749571 S2P_Cfg11__03: 8 SBMU
 SG_ S2P_Cfg11_HW_Ver_Byte9_03 : 0|8@1+ (1,0) [0|255] ""  PC
 SG_ S2P_Cfg11_HW_Ver_Byte10_03 : 8|8@1+ (1,0) [0|255] ""  PC
 SG_ S2P_Cfg11_HW_Ver_Byte11_03 : 16|8@1+ (1,0) [0|255] ""  PC
 SG_ S2P_Cfg11_HW_Ver_Byte12_03 : 24|8@1+ (1,0) [0|255] ""  PC
 SG_ S2P_Cfg11_HW_Ver_Byte13_03 : 32|8@1+ (1,0) [0|255] ""  PC
 SG_ S2P_Cfg11_HW_Ver_Byte14_03 : 40|8@1+ (1,0) [0|255] ""  PC
 SG_ S2P_Cfg11_HW_Ver_Byte15_03 : 48|8@1+ (1,0) [0|255] ""  PC
 SG_ S2P_Cfg11_HW_Ver_Byte16_03 : 56|8@1+ (1,0) [0|255] ""  PC

BO_ 2417749572 S2P_Cfg11__04: 8 SBMU
 SG_ S2P_Cfg11_HW_Ver_Byte9_04 : 0|8@1+ (1,0) [0|255] ""  PC
 SG_ S2P_Cfg11_HW_Ver_Byte10_04 : 8|8@1+ (1,0) [0|255] ""  PC
 SG_ S2P_Cfg11_HW_Ver_Byte11_04 : 16|8@1+ (1,0) [0|255] ""  PC
 SG_ S2P_Cfg11_HW_Ver_Byte12_04 : 24|8@1+ (1,0) [0|255] ""  PC
 SG_ S2P_Cfg11_HW_Ver_Byte13_04 : 32|8@1+ (1,0) [0|255] ""  PC
 SG_ S2P_Cfg11_HW_Ver_Byte14_04 : 40|8@1+ (1,0) [0|255] ""  PC
 SG_ S2P_Cfg11_HW_Ver_Byte15_04 : 48|8@1+ (1,0) [0|255] ""  PC
 SG_ S2P_Cfg11_HW_Ver_Byte16_04 : 56|8@1+ (1,0) [0|255] ""  PC

BO_ 2417749573 S2P_Cfg11__05: 8 SBMU
 SG_ S2P_Cfg11_HW_Ver_Byte9_05 : 0|8@1+ (1,0) [0|255] ""  PC
 SG_ S2P_Cfg11_HW_Ver_Byte10_05 : 8|8@1+ (1,0) [0|255] ""  PC
 SG_ S2P_Cfg11_HW_Ver_Byte11_05 : 16|8@1+ (1,0) [0|255] ""  PC
 SG_ S2P_Cfg11_HW_Ver_Byte12_05 : 24|8@1+ (1,0) [0|255] ""  PC
 SG_ S2P_Cfg11_HW_Ver_Byte13_05 : 32|8@1+ (1,0) [0|255] ""  PC
 SG_ S2P_Cfg11_HW_Ver_Byte14_05 : 40|8@1+ (1,0) [0|255] ""  PC
 SG_ S2P_Cfg11_HW_Ver_Byte15_05 : 48|8@1+ (1,0) [0|255] ""  PC
 SG_ S2P_Cfg11_HW_Ver_Byte16_05 : 56|8@1+ (1,0) [0|255] ""  PC

BO_ 2417749574 S2P_Cfg11__06: 8 SBMU
 SG_ S2P_Cfg11_HW_Ver_Byte9_06 : 0|8@1+ (1,0) [0|255] ""  PC
 SG_ S2P_Cfg11_HW_Ver_Byte10_06 : 8|8@1+ (1,0) [0|255] ""  PC
 SG_ S2P_Cfg11_HW_Ver_Byte11_06 : 16|8@1+ (1,0) [0|255] ""  PC
 SG_ S2P_Cfg11_HW_Ver_Byte12_06 : 24|8@1+ (1,0) [0|255] ""  PC
 SG_ S2P_Cfg11_HW_Ver_Byte13_06 : 32|8@1+ (1,0) [0|255] ""  PC
 SG_ S2P_Cfg11_HW_Ver_Byte14_06 : 40|8@1+ (1,0) [0|255] ""  PC
 SG_ S2P_Cfg11_HW_Ver_Byte15_06 : 48|8@1+ (1,0) [0|255] ""  PC
 SG_ S2P_Cfg11_HW_Ver_Byte16_06 : 56|8@1+ (1,0) [0|255] ""  PC

BO_ 2417749575 S2P_Cfg11__07: 8 SBMU
 SG_ S2P_Cfg11_HW_Ver_Byte9_07 : 0|8@1+ (1,0) [0|255] ""  PC
 SG_ S2P_Cfg11_HW_Ver_Byte10_07 : 8|8@1+ (1,0) [0|255] ""  PC
 SG_ S2P_Cfg11_HW_Ver_Byte11_07 : 16|8@1+ (1,0) [0|255] ""  PC
 SG_ S2P_Cfg11_HW_Ver_Byte12_07 : 24|8@1+ (1,0) [0|255] ""  PC
 SG_ S2P_Cfg11_HW_Ver_Byte13_07 : 32|8@1+ (1,0) [0|255] ""  PC
 SG_ S2P_Cfg11_HW_Ver_Byte14_07 : 40|8@1+ (1,0) [0|255] ""  PC
 SG_ S2P_Cfg11_HW_Ver_Byte15_07 : 48|8@1+ (1,0) [0|255] ""  PC
 SG_ S2P_Cfg11_HW_Ver_Byte16_07 : 56|8@1+ (1,0) [0|255] ""  PC

BO_ 2417749576 S2P_Cfg11__08: 8 SBMU
 SG_ S2P_Cfg11_HW_Ver_Byte9_08 : 0|8@1+ (1,0) [0|255] ""  PC
 SG_ S2P_Cfg11_HW_Ver_Byte10_08 : 8|8@1+ (1,0) [0|255] ""  PC
 SG_ S2P_Cfg11_HW_Ver_Byte11_08 : 16|8@1+ (1,0) [0|255] ""  PC
 SG_ S2P_Cfg11_HW_Ver_Byte12_08 : 24|8@1+ (1,0) [0|255] ""  PC
 SG_ S2P_Cfg11_HW_Ver_Byte13_08 : 32|8@1+ (1,0) [0|255] ""  PC
 SG_ S2P_Cfg11_HW_Ver_Byte14_08 : 40|8@1+ (1,0) [0|255] ""  PC
 SG_ S2P_Cfg11_HW_Ver_Byte15_08 : 48|8@1+ (1,0) [0|255] ""  PC
 SG_ S2P_Cfg11_HW_Ver_Byte16_08 : 56|8@1+ (1,0) [0|255] ""  PC

BO_ 2417749577 S2P_Cfg11__09: 8 SBMU
 SG_ S2P_Cfg11_HW_Ver_Byte9_09 : 0|8@1+ (1,0) [0|255] ""  PC
 SG_ S2P_Cfg11_HW_Ver_Byte10_09 : 8|8@1+ (1,0) [0|255] ""  PC
 SG_ S2P_Cfg11_HW_Ver_Byte11_09 : 16|8@1+ (1,0) [0|255] ""  PC
 SG_ S2P_Cfg11_HW_Ver_Byte12_09 : 24|8@1+ (1,0) [0|255] ""  PC
 SG_ S2P_Cfg11_HW_Ver_Byte13_09 : 32|8@1+ (1,0) [0|255] ""  PC
 SG_ S2P_Cfg11_HW_Ver_Byte14_09 : 40|8@1+ (1,0) [0|255] ""  PC
 SG_ S2P_Cfg11_HW_Ver_Byte15_09 : 48|8@1+ (1,0) [0|255] ""  PC
 SG_ S2P_Cfg11_HW_Ver_Byte16_09 : 56|8@1+ (1,0) [0|255] ""  PC

BO_ 2417749578 S2P_Cfg11__10: 8 SBMU
 SG_ S2P_Cfg11_HW_Ver_Byte9_10 : 0|8@1+ (1,0) [0|255] ""  PC
 SG_ S2P_Cfg11_HW_Ver_Byte10_10 : 8|8@1+ (1,0) [0|255] ""  PC
 SG_ S2P_Cfg11_HW_Ver_Byte11_10 : 16|8@1+ (1,0) [0|255] ""  PC
 SG_ S2P_Cfg11_HW_Ver_Byte12_10 : 24|8@1+ (1,0) [0|255] ""  PC
 SG_ S2P_Cfg11_HW_Ver_Byte13_10 : 32|8@1+ (1,0) [0|255] ""  PC
 SG_ S2P_Cfg11_HW_Ver_Byte14_10 : 40|8@1+ (1,0) [0|255] ""  PC
 SG_ S2P_Cfg11_HW_Ver_Byte15_10 : 48|8@1+ (1,0) [0|255] ""  PC
 SG_ S2P_Cfg11_HW_Ver_Byte16_10 : 56|8@1+ (1,0) [0|255] ""  PC

BO_ 2417749579 S2P_Cfg11__11: 8 SBMU
 SG_ S2P_Cfg11_HW_Ver_Byte9_11 : 0|8@1+ (1,0) [0|255] ""  PC
 SG_ S2P_Cfg11_HW_Ver_Byte10_11 : 8|8@1+ (1,0) [0|255] ""  PC
 SG_ S2P_Cfg11_HW_Ver_Byte11_11 : 16|8@1+ (1,0) [0|255] ""  PC
 SG_ S2P_Cfg11_HW_Ver_Byte12_11 : 24|8@1+ (1,0) [0|255] ""  PC
 SG_ S2P_Cfg11_HW_Ver_Byte13_11 : 32|8@1+ (1,0) [0|255] ""  PC
 SG_ S2P_Cfg11_HW_Ver_Byte14_11 : 40|8@1+ (1,0) [0|255] ""  PC
 SG_ S2P_Cfg11_HW_Ver_Byte15_11 : 48|8@1+ (1,0) [0|255] ""  PC
 SG_ S2P_Cfg11_HW_Ver_Byte16_11 : 56|8@1+ (1,0) [0|255] ""  PC

BO_ 2417749580 S2P_Cfg11__12: 8 SBMU
 SG_ S2P_Cfg11_HW_Ver_Byte9_12 : 0|8@1+ (1,0) [0|255] ""  PC
 SG_ S2P_Cfg11_HW_Ver_Byte10_12 : 8|8@1+ (1,0) [0|255] ""  PC
 SG_ S2P_Cfg11_HW_Ver_Byte11_12 : 16|8@1+ (1,0) [0|255] ""  PC
 SG_ S2P_Cfg11_HW_Ver_Byte12_12 : 24|8@1+ (1,0) [0|255] ""  PC
 SG_ S2P_Cfg11_HW_Ver_Byte13_12 : 32|8@1+ (1,0) [0|255] ""  PC
 SG_ S2P_Cfg11_HW_Ver_Byte14_12 : 40|8@1+ (1,0) [0|255] ""  PC
 SG_ S2P_Cfg11_HW_Ver_Byte15_12 : 48|8@1+ (1,0) [0|255] ""  PC
 SG_ S2P_Cfg11_HW_Ver_Byte16_12 : 56|8@1+ (1,0) [0|255] ""  PC

BO_ 2417749581 S2P_Cfg11__13: 8 SBMU
 SG_ S2P_Cfg11_HW_Ver_Byte9_13 : 0|8@1+ (1,0) [0|255] ""  PC
 SG_ S2P_Cfg11_HW_Ver_Byte10_13 : 8|8@1+ (1,0) [0|255] ""  PC
 SG_ S2P_Cfg11_HW_Ver_Byte11_13 : 16|8@1+ (1,0) [0|255] ""  PC
 SG_ S2P_Cfg11_HW_Ver_Byte12_13 : 24|8@1+ (1,0) [0|255] ""  PC
 SG_ S2P_Cfg11_HW_Ver_Byte13_13 : 32|8@1+ (1,0) [0|255] ""  PC
 SG_ S2P_Cfg11_HW_Ver_Byte14_13 : 40|8@1+ (1,0) [0|255] ""  PC
 SG_ S2P_Cfg11_HW_Ver_Byte15_13 : 48|8@1+ (1,0) [0|255] ""  PC
 SG_ S2P_Cfg11_HW_Ver_Byte16_13 : 56|8@1+ (1,0) [0|255] ""  PC

BO_ 2417749582 S2P_Cfg11__14: 8 SBMU
 SG_ S2P_Cfg11_HW_Ver_Byte9_14 : 0|8@1+ (1,0) [0|255] ""  PC
 SG_ S2P_Cfg11_HW_Ver_Byte10_14 : 8|8@1+ (1,0) [0|255] ""  PC
 SG_ S2P_Cfg11_HW_Ver_Byte11_14 : 16|8@1+ (1,0) [0|255] ""  PC
 SG_ S2P_Cfg11_HW_Ver_Byte12_14 : 24|8@1+ (1,0) [0|255] ""  PC
 SG_ S2P_Cfg11_HW_Ver_Byte13_14 : 32|8@1+ (1,0) [0|255] ""  PC
 SG_ S2P_Cfg11_HW_Ver_Byte14_14 : 40|8@1+ (1,0) [0|255] ""  PC
 SG_ S2P_Cfg11_HW_Ver_Byte15_14 : 48|8@1+ (1,0) [0|255] ""  PC
 SG_ S2P_Cfg11_HW_Ver_Byte16_14 : 56|8@1+ (1,0) [0|255] ""  PC

BO_ 2417749583 S2P_Cfg11__15: 8 SBMU
 SG_ S2P_Cfg11_HW_Ver_Byte9_15 : 0|8@1+ (1,0) [0|255] ""  PC
 SG_ S2P_Cfg11_HW_Ver_Byte10_15 : 8|8@1+ (1,0) [0|255] ""  PC
 SG_ S2P_Cfg11_HW_Ver_Byte11_15 : 16|8@1+ (1,0) [0|255] ""  PC
 SG_ S2P_Cfg11_HW_Ver_Byte12_15 : 24|8@1+ (1,0) [0|255] ""  PC
 SG_ S2P_Cfg11_HW_Ver_Byte13_15 : 32|8@1+ (1,0) [0|255] ""  PC
 SG_ S2P_Cfg11_HW_Ver_Byte14_15 : 40|8@1+ (1,0) [0|255] ""  PC
 SG_ S2P_Cfg11_HW_Ver_Byte15_15 : 48|8@1+ (1,0) [0|255] ""  PC
 SG_ S2P_Cfg11_HW_Ver_Byte16_15 : 56|8@1+ (1,0) [0|255] ""  PC

BO_ 2417749584 S2P_Cfg11__16: 8 SBMU
 SG_ S2P_Cfg11_HW_Ver_Byte9_16 : 0|8@1+ (1,0) [0|255] ""  PC
 SG_ S2P_Cfg11_HW_Ver_Byte10_16 : 8|8@1+ (1,0) [0|255] ""  PC
 SG_ S2P_Cfg11_HW_Ver_Byte11_16 : 16|8@1+ (1,0) [0|255] ""  PC
 SG_ S2P_Cfg11_HW_Ver_Byte12_16 : 24|8@1+ (1,0) [0|255] ""  PC
 SG_ S2P_Cfg11_HW_Ver_Byte13_16 : 32|8@1+ (1,0) [0|255] ""  PC
 SG_ S2P_Cfg11_HW_Ver_Byte14_16 : 40|8@1+ (1,0) [0|255] ""  PC
 SG_ S2P_Cfg11_HW_Ver_Byte15_16 : 48|8@1+ (1,0) [0|255] ""  PC
 SG_ S2P_Cfg11_HW_Ver_Byte16_16 : 56|8@1+ (1,0) [0|255] ""  PC

BO_ 2417749585 S2P_Cfg11__17: 8 SBMU
 SG_ S2P_Cfg11_HW_Ver_Byte9_17 : 0|8@1+ (1,0) [0|255] ""  PC
 SG_ S2P_Cfg11_HW_Ver_Byte10_17 : 8|8@1+ (1,0) [0|255] ""  PC
 SG_ S2P_Cfg11_HW_Ver_Byte11_17 : 16|8@1+ (1,0) [0|255] ""  PC
 SG_ S2P_Cfg11_HW_Ver_Byte12_17 : 24|8@1+ (1,0) [0|255] ""  PC
 SG_ S2P_Cfg11_HW_Ver_Byte13_17 : 32|8@1+ (1,0) [0|255] ""  PC
 SG_ S2P_Cfg11_HW_Ver_Byte14_17 : 40|8@1+ (1,0) [0|255] ""  PC
 SG_ S2P_Cfg11_HW_Ver_Byte15_17 : 48|8@1+ (1,0) [0|255] ""  PC
 SG_ S2P_Cfg11_HW_Ver_Byte16_17 : 56|8@1+ (1,0) [0|255] ""  PC

BO_ 2417749586 S2P_Cfg11__18: 8 SBMU
 SG_ S2P_Cfg11_HW_Ver_Byte9_18 : 0|8@1+ (1,0) [0|255] ""  PC
 SG_ S2P_Cfg11_HW_Ver_Byte10_18 : 8|8@1+ (1,0) [0|255] ""  PC
 SG_ S2P_Cfg11_HW_Ver_Byte11_18 : 16|8@1+ (1,0) [0|255] ""  PC
 SG_ S2P_Cfg11_HW_Ver_Byte12_18 : 24|8@1+ (1,0) [0|255] ""  PC
 SG_ S2P_Cfg11_HW_Ver_Byte13_18 : 32|8@1+ (1,0) [0|255] ""  PC
 SG_ S2P_Cfg11_HW_Ver_Byte14_18 : 40|8@1+ (1,0) [0|255] ""  PC
 SG_ S2P_Cfg11_HW_Ver_Byte15_18 : 48|8@1+ (1,0) [0|255] ""  PC
 SG_ S2P_Cfg11_HW_Ver_Byte16_18 : 56|8@1+ (1,0) [0|255] ""  PC

BO_ 2417749587 S2P_Cfg11__19: 8 SBMU
 SG_ S2P_Cfg11_HW_Ver_Byte9_19 : 0|8@1+ (1,0) [0|255] ""  PC
 SG_ S2P_Cfg11_HW_Ver_Byte10_19 : 8|8@1+ (1,0) [0|255] ""  PC
 SG_ S2P_Cfg11_HW_Ver_Byte11_19 : 16|8@1+ (1,0) [0|255] ""  PC
 SG_ S2P_Cfg11_HW_Ver_Byte12_19 : 24|8@1+ (1,0) [0|255] ""  PC
 SG_ S2P_Cfg11_HW_Ver_Byte13_19 : 32|8@1+ (1,0) [0|255] ""  PC
 SG_ S2P_Cfg11_HW_Ver_Byte14_19 : 40|8@1+ (1,0) [0|255] ""  PC
 SG_ S2P_Cfg11_HW_Ver_Byte15_19 : 48|8@1+ (1,0) [0|255] ""  PC
 SG_ S2P_Cfg11_HW_Ver_Byte16_19 : 56|8@1+ (1,0) [0|255] ""  PC

BO_ 2417749588 S2P_Cfg11__20: 8 SBMU
 SG_ S2P_Cfg11_HW_Ver_Byte9_20 : 0|8@1+ (1,0) [0|255] ""  PC
 SG_ S2P_Cfg11_HW_Ver_Byte10_20 : 8|8@1+ (1,0) [0|255] ""  PC
 SG_ S2P_Cfg11_HW_Ver_Byte11_20 : 16|8@1+ (1,0) [0|255] ""  PC
 SG_ S2P_Cfg11_HW_Ver_Byte12_20 : 24|8@1+ (1,0) [0|255] ""  PC
 SG_ S2P_Cfg11_HW_Ver_Byte13_20 : 32|8@1+ (1,0) [0|255] ""  PC
 SG_ S2P_Cfg11_HW_Ver_Byte14_20 : 40|8@1+ (1,0) [0|255] ""  PC
 SG_ S2P_Cfg11_HW_Ver_Byte15_20 : 48|8@1+ (1,0) [0|255] ""  PC
 SG_ S2P_Cfg11_HW_Ver_Byte16_20 : 56|8@1+ (1,0) [0|255] ""  PC

BO_ 2417749589 S2P_Cfg11__21: 8 SBMU
 SG_ S2P_Cfg11_HW_Ver_Byte9_21 : 0|8@1+ (1,0) [0|255] ""  PC
 SG_ S2P_Cfg11_HW_Ver_Byte10_21 : 8|8@1+ (1,0) [0|255] ""  PC
 SG_ S2P_Cfg11_HW_Ver_Byte11_21 : 16|8@1+ (1,0) [0|255] ""  PC
 SG_ S2P_Cfg11_HW_Ver_Byte12_21 : 24|8@1+ (1,0) [0|255] ""  PC
 SG_ S2P_Cfg11_HW_Ver_Byte13_21 : 32|8@1+ (1,0) [0|255] ""  PC
 SG_ S2P_Cfg11_HW_Ver_Byte14_21 : 40|8@1+ (1,0) [0|255] ""  PC
 SG_ S2P_Cfg11_HW_Ver_Byte15_21 : 48|8@1+ (1,0) [0|255] ""  PC
 SG_ S2P_Cfg11_HW_Ver_Byte16_21 : 56|8@1+ (1,0) [0|255] ""  PC

BO_ 2417749590 S2P_Cfg11__22: 8 SBMU
 SG_ S2P_Cfg11_HW_Ver_Byte9_22 : 0|8@1+ (1,0) [0|255] ""  PC
 SG_ S2P_Cfg11_HW_Ver_Byte10_22 : 8|8@1+ (1,0) [0|255] ""  PC
 SG_ S2P_Cfg11_HW_Ver_Byte11_22 : 16|8@1+ (1,0) [0|255] ""  PC
 SG_ S2P_Cfg11_HW_Ver_Byte12_22 : 24|8@1+ (1,0) [0|255] ""  PC
 SG_ S2P_Cfg11_HW_Ver_Byte13_22 : 32|8@1+ (1,0) [0|255] ""  PC
 SG_ S2P_Cfg11_HW_Ver_Byte14_22 : 40|8@1+ (1,0) [0|255] ""  PC
 SG_ S2P_Cfg11_HW_Ver_Byte15_22 : 48|8@1+ (1,0) [0|255] ""  PC
 SG_ S2P_Cfg11_HW_Ver_Byte16_22 : 56|8@1+ (1,0) [0|255] ""  PC

BO_ 2417749591 S2P_Cfg11__23: 8 SBMU
 SG_ S2P_Cfg11_HW_Ver_Byte9_23 : 0|8@1+ (1,0) [0|255] ""  PC
 SG_ S2P_Cfg11_HW_Ver_Byte10_23 : 8|8@1+ (1,0) [0|255] ""  PC
 SG_ S2P_Cfg11_HW_Ver_Byte11_23 : 16|8@1+ (1,0) [0|255] ""  PC
 SG_ S2P_Cfg11_HW_Ver_Byte12_23 : 24|8@1+ (1,0) [0|255] ""  PC
 SG_ S2P_Cfg11_HW_Ver_Byte13_23 : 32|8@1+ (1,0) [0|255] ""  PC
 SG_ S2P_Cfg11_HW_Ver_Byte14_23 : 40|8@1+ (1,0) [0|255] ""  PC
 SG_ S2P_Cfg11_HW_Ver_Byte15_23 : 48|8@1+ (1,0) [0|255] ""  PC
 SG_ S2P_Cfg11_HW_Ver_Byte16_23 : 56|8@1+ (1,0) [0|255] ""  PC

BO_ 2417749592 S2P_Cfg11__24: 8 SBMU
 SG_ S2P_Cfg11_HW_Ver_Byte9_24 : 0|8@1+ (1,0) [0|255] ""  PC
 SG_ S2P_Cfg11_HW_Ver_Byte10_24 : 8|8@1+ (1,0) [0|255] ""  PC
 SG_ S2P_Cfg11_HW_Ver_Byte11_24 : 16|8@1+ (1,0) [0|255] ""  PC
 SG_ S2P_Cfg11_HW_Ver_Byte12_24 : 24|8@1+ (1,0) [0|255] ""  PC
 SG_ S2P_Cfg11_HW_Ver_Byte13_24 : 32|8@1+ (1,0) [0|255] ""  PC
 SG_ S2P_Cfg11_HW_Ver_Byte14_24 : 40|8@1+ (1,0) [0|255] ""  PC
 SG_ S2P_Cfg11_HW_Ver_Byte15_24 : 48|8@1+ (1,0) [0|255] ""  PC
 SG_ S2P_Cfg11_HW_Ver_Byte16_24 : 56|8@1+ (1,0) [0|255] ""  PC

BO_ 2417749593 S2P_Cfg11__25: 8 SBMU
 SG_ S2P_Cfg11_HW_Ver_Byte9_25 : 0|8@1+ (1,0) [0|255] ""  PC
 SG_ S2P_Cfg11_HW_Ver_Byte10_25 : 8|8@1+ (1,0) [0|255] ""  PC
 SG_ S2P_Cfg11_HW_Ver_Byte11_25 : 16|8@1+ (1,0) [0|255] ""  PC
 SG_ S2P_Cfg11_HW_Ver_Byte12_25 : 24|8@1+ (1,0) [0|255] ""  PC
 SG_ S2P_Cfg11_HW_Ver_Byte13_25 : 32|8@1+ (1,0) [0|255] ""  PC
 SG_ S2P_Cfg11_HW_Ver_Byte14_25 : 40|8@1+ (1,0) [0|255] ""  PC
 SG_ S2P_Cfg11_HW_Ver_Byte15_25 : 48|8@1+ (1,0) [0|255] ""  PC
 SG_ S2P_Cfg11_HW_Ver_Byte16_25 : 56|8@1+ (1,0) [0|255] ""  PC

BO_ 2417749594 S2P_Cfg11__26: 8 SBMU
 SG_ S2P_Cfg11_HW_Ver_Byte9_26 : 0|8@1+ (1,0) [0|255] ""  PC
 SG_ S2P_Cfg11_HW_Ver_Byte10_26 : 8|8@1+ (1,0) [0|255] ""  PC
 SG_ S2P_Cfg11_HW_Ver_Byte11_26 : 16|8@1+ (1,0) [0|255] ""  PC
 SG_ S2P_Cfg11_HW_Ver_Byte12_26 : 24|8@1+ (1,0) [0|255] ""  PC
 SG_ S2P_Cfg11_HW_Ver_Byte13_26 : 32|8@1+ (1,0) [0|255] ""  PC
 SG_ S2P_Cfg11_HW_Ver_Byte14_26 : 40|8@1+ (1,0) [0|255] ""  PC
 SG_ S2P_Cfg11_HW_Ver_Byte15_26 : 48|8@1+ (1,0) [0|255] ""  PC
 SG_ S2P_Cfg11_HW_Ver_Byte16_26 : 56|8@1+ (1,0) [0|255] ""  PC

BO_ 2417749595 S2P_Cfg11__27: 8 SBMU
 SG_ S2P_Cfg11_HW_Ver_Byte9_27 : 0|8@1+ (1,0) [0|255] ""  PC
 SG_ S2P_Cfg11_HW_Ver_Byte10_27 : 8|8@1+ (1,0) [0|255] ""  PC
 SG_ S2P_Cfg11_HW_Ver_Byte11_27 : 16|8@1+ (1,0) [0|255] ""  PC
 SG_ S2P_Cfg11_HW_Ver_Byte12_27 : 24|8@1+ (1,0) [0|255] ""  PC
 SG_ S2P_Cfg11_HW_Ver_Byte13_27 : 32|8@1+ (1,0) [0|255] ""  PC
 SG_ S2P_Cfg11_HW_Ver_Byte14_27 : 40|8@1+ (1,0) [0|255] ""  PC
 SG_ S2P_Cfg11_HW_Ver_Byte15_27 : 48|8@1+ (1,0) [0|255] ""  PC
 SG_ S2P_Cfg11_HW_Ver_Byte16_27 : 56|8@1+ (1,0) [0|255] ""  PC

BO_ 2417749596 S2P_Cfg11__28: 8 SBMU
 SG_ S2P_Cfg11_HW_Ver_Byte9_28 : 0|8@1+ (1,0) [0|255] ""  PC
 SG_ S2P_Cfg11_HW_Ver_Byte10_28 : 8|8@1+ (1,0) [0|255] ""  PC
 SG_ S2P_Cfg11_HW_Ver_Byte11_28 : 16|8@1+ (1,0) [0|255] ""  PC
 SG_ S2P_Cfg11_HW_Ver_Byte12_28 : 24|8@1+ (1,0) [0|255] ""  PC
 SG_ S2P_Cfg11_HW_Ver_Byte13_28 : 32|8@1+ (1,0) [0|255] ""  PC
 SG_ S2P_Cfg11_HW_Ver_Byte14_28 : 40|8@1+ (1,0) [0|255] ""  PC
 SG_ S2P_Cfg11_HW_Ver_Byte15_28 : 48|8@1+ (1,0) [0|255] ""  PC
 SG_ S2P_Cfg11_HW_Ver_Byte16_28 : 56|8@1+ (1,0) [0|255] ""  PC

BO_ 2417749597 S2P_Cfg11__29: 8 SBMU
 SG_ S2P_Cfg11_HW_Ver_Byte9_29 : 0|8@1+ (1,0) [0|255] ""  PC
 SG_ S2P_Cfg11_HW_Ver_Byte10_29 : 8|8@1+ (1,0) [0|255] ""  PC
 SG_ S2P_Cfg11_HW_Ver_Byte11_29 : 16|8@1+ (1,0) [0|255] ""  PC
 SG_ S2P_Cfg11_HW_Ver_Byte12_29 : 24|8@1+ (1,0) [0|255] ""  PC
 SG_ S2P_Cfg11_HW_Ver_Byte13_29 : 32|8@1+ (1,0) [0|255] ""  PC
 SG_ S2P_Cfg11_HW_Ver_Byte14_29 : 40|8@1+ (1,0) [0|255] ""  PC
 SG_ S2P_Cfg11_HW_Ver_Byte15_29 : 48|8@1+ (1,0) [0|255] ""  PC
 SG_ S2P_Cfg11_HW_Ver_Byte16_29 : 56|8@1+ (1,0) [0|255] ""  PC

BO_ 2417749598 S2P_Cfg11__30: 8 SBMU
 SG_ S2P_Cfg11_HW_Ver_Byte9_30 : 0|8@1+ (1,0) [0|255] ""  PC
 SG_ S2P_Cfg11_HW_Ver_Byte10_30 : 8|8@1+ (1,0) [0|255] ""  PC
 SG_ S2P_Cfg11_HW_Ver_Byte11_30 : 16|8@1+ (1,0) [0|255] ""  PC
 SG_ S2P_Cfg11_HW_Ver_Byte12_30 : 24|8@1+ (1,0) [0|255] ""  PC
 SG_ S2P_Cfg11_HW_Ver_Byte13_30 : 32|8@1+ (1,0) [0|255] ""  PC
 SG_ S2P_Cfg11_HW_Ver_Byte14_30 : 40|8@1+ (1,0) [0|255] ""  PC
 SG_ S2P_Cfg11_HW_Ver_Byte15_30 : 48|8@1+ (1,0) [0|255] ""  PC
 SG_ S2P_Cfg11_HW_Ver_Byte16_30 : 56|8@1+ (1,0) [0|255] ""  PC

BO_ 2417749599 S2P_Cfg11__31: 8 SBMU
 SG_ S2P_Cfg11_HW_Ver_Byte9_31 : 0|8@1+ (1,0) [0|255] ""  PC
 SG_ S2P_Cfg11_HW_Ver_Byte10_31 : 8|8@1+ (1,0) [0|255] ""  PC
 SG_ S2P_Cfg11_HW_Ver_Byte11_31 : 16|8@1+ (1,0) [0|255] ""  PC
 SG_ S2P_Cfg11_HW_Ver_Byte12_31 : 24|8@1+ (1,0) [0|255] ""  PC
 SG_ S2P_Cfg11_HW_Ver_Byte13_31 : 32|8@1+ (1,0) [0|255] ""  PC
 SG_ S2P_Cfg11_HW_Ver_Byte14_31 : 40|8@1+ (1,0) [0|255] ""  PC
 SG_ S2P_Cfg11_HW_Ver_Byte15_31 : 48|8@1+ (1,0) [0|255] ""  PC
 SG_ S2P_Cfg11_HW_Ver_Byte16_31 : 56|8@1+ (1,0) [0|255] ""  PC

BO_ 2417749600 S2P_Cfg11__32: 8 SBMU
 SG_ S2P_Cfg11_HW_Ver_Byte9_32 : 0|8@1+ (1,0) [0|255] ""  PC
 SG_ S2P_Cfg11_HW_Ver_Byte10_32 : 8|8@1+ (1,0) [0|255] ""  PC
 SG_ S2P_Cfg11_HW_Ver_Byte11_32 : 16|8@1+ (1,0) [0|255] ""  PC
 SG_ S2P_Cfg11_HW_Ver_Byte12_32 : 24|8@1+ (1,0) [0|255] ""  PC
 SG_ S2P_Cfg11_HW_Ver_Byte13_32 : 32|8@1+ (1,0) [0|255] ""  PC
 SG_ S2P_Cfg11_HW_Ver_Byte14_32 : 40|8@1+ (1,0) [0|255] ""  PC
 SG_ S2P_Cfg11_HW_Ver_Byte15_32 : 48|8@1+ (1,0) [0|255] ""  PC
 SG_ S2P_Cfg11_HW_Ver_Byte16_32 : 56|8@1+ (1,0) [0|255] ""  PC

BO_ 2417749601 S2P_Cfg11__33: 8 SBMU
 SG_ S2P_Cfg11_HW_Ver_Byte9_33 : 0|8@1+ (1,0) [0|255] ""  PC
 SG_ S2P_Cfg11_HW_Ver_Byte10_33 : 8|8@1+ (1,0) [0|255] ""  PC
 SG_ S2P_Cfg11_HW_Ver_Byte11_33 : 16|8@1+ (1,0) [0|255] ""  PC
 SG_ S2P_Cfg11_HW_Ver_Byte12_33 : 24|8@1+ (1,0) [0|255] ""  PC
 SG_ S2P_Cfg11_HW_Ver_Byte13_33 : 32|8@1+ (1,0) [0|255] ""  PC
 SG_ S2P_Cfg11_HW_Ver_Byte14_33 : 40|8@1+ (1,0) [0|255] ""  PC
 SG_ S2P_Cfg11_HW_Ver_Byte15_33 : 48|8@1+ (1,0) [0|255] ""  PC
 SG_ S2P_Cfg11_HW_Ver_Byte16_33 : 56|8@1+ (1,0) [0|255] ""  PC

BO_ 2417749602 S2P_Cfg11__34: 8 SBMU
 SG_ S2P_Cfg11_HW_Ver_Byte9_34 : 0|8@1+ (1,0) [0|255] ""  PC
 SG_ S2P_Cfg11_HW_Ver_Byte10_34 : 8|8@1+ (1,0) [0|255] ""  PC
 SG_ S2P_Cfg11_HW_Ver_Byte11_34 : 16|8@1+ (1,0) [0|255] ""  PC
 SG_ S2P_Cfg11_HW_Ver_Byte12_34 : 24|8@1+ (1,0) [0|255] ""  PC
 SG_ S2P_Cfg11_HW_Ver_Byte13_34 : 32|8@1+ (1,0) [0|255] ""  PC
 SG_ S2P_Cfg11_HW_Ver_Byte14_34 : 40|8@1+ (1,0) [0|255] ""  PC
 SG_ S2P_Cfg11_HW_Ver_Byte15_34 : 48|8@1+ (1,0) [0|255] ""  PC
 SG_ S2P_Cfg11_HW_Ver_Byte16_34 : 56|8@1+ (1,0) [0|255] ""  PC

BO_ 2417749603 S2P_Cfg11__35: 8 SBMU
 SG_ S2P_Cfg11_HW_Ver_Byte9_35 : 0|8@1+ (1,0) [0|255] ""  PC
 SG_ S2P_Cfg11_HW_Ver_Byte10_35 : 8|8@1+ (1,0) [0|255] ""  PC
 SG_ S2P_Cfg11_HW_Ver_Byte11_35 : 16|8@1+ (1,0) [0|255] ""  PC
 SG_ S2P_Cfg11_HW_Ver_Byte12_35 : 24|8@1+ (1,0) [0|255] ""  PC
 SG_ S2P_Cfg11_HW_Ver_Byte13_35 : 32|8@1+ (1,0) [0|255] ""  PC
 SG_ S2P_Cfg11_HW_Ver_Byte14_35 : 40|8@1+ (1,0) [0|255] ""  PC
 SG_ S2P_Cfg11_HW_Ver_Byte15_35 : 48|8@1+ (1,0) [0|255] ""  PC
 SG_ S2P_Cfg11_HW_Ver_Byte16_35 : 56|8@1+ (1,0) [0|255] ""  PC

BO_ 2417749604 S2P_Cfg11__36: 8 SBMU
 SG_ S2P_Cfg11_HW_Ver_Byte9_36 : 0|8@1+ (1,0) [0|255] ""  PC
 SG_ S2P_Cfg11_HW_Ver_Byte10_36 : 8|8@1+ (1,0) [0|255] ""  PC
 SG_ S2P_Cfg11_HW_Ver_Byte11_36 : 16|8@1+ (1,0) [0|255] ""  PC
 SG_ S2P_Cfg11_HW_Ver_Byte12_36 : 24|8@1+ (1,0) [0|255] ""  PC
 SG_ S2P_Cfg11_HW_Ver_Byte13_36 : 32|8@1+ (1,0) [0|255] ""  PC
 SG_ S2P_Cfg11_HW_Ver_Byte14_36 : 40|8@1+ (1,0) [0|255] ""  PC
 SG_ S2P_Cfg11_HW_Ver_Byte15_36 : 48|8@1+ (1,0) [0|255] ""  PC
 SG_ S2P_Cfg11_HW_Ver_Byte16_36 : 56|8@1+ (1,0) [0|255] ""  PC

BO_ 2417749605 S2P_Cfg11__37: 8 SBMU
 SG_ S2P_Cfg11_HW_Ver_Byte9_37 : 0|8@1+ (1,0) [0|255] ""  PC
 SG_ S2P_Cfg11_HW_Ver_Byte10_37 : 8|8@1+ (1,0) [0|255] ""  PC
 SG_ S2P_Cfg11_HW_Ver_Byte11_37 : 16|8@1+ (1,0) [0|255] ""  PC
 SG_ S2P_Cfg11_HW_Ver_Byte12_37 : 24|8@1+ (1,0) [0|255] ""  PC
 SG_ S2P_Cfg11_HW_Ver_Byte13_37 : 32|8@1+ (1,0) [0|255] ""  PC
 SG_ S2P_Cfg11_HW_Ver_Byte14_37 : 40|8@1+ (1,0) [0|255] ""  PC
 SG_ S2P_Cfg11_HW_Ver_Byte15_37 : 48|8@1+ (1,0) [0|255] ""  PC
 SG_ S2P_Cfg11_HW_Ver_Byte16_37 : 56|8@1+ (1,0) [0|255] ""  PC

BO_ 2417749606 S2P_Cfg11__38: 8 SBMU
 SG_ S2P_Cfg11_HW_Ver_Byte9_38 : 0|8@1+ (1,0) [0|255] ""  PC
 SG_ S2P_Cfg11_HW_Ver_Byte10_38 : 8|8@1+ (1,0) [0|255] ""  PC
 SG_ S2P_Cfg11_HW_Ver_Byte11_38 : 16|8@1+ (1,0) [0|255] ""  PC
 SG_ S2P_Cfg11_HW_Ver_Byte12_38 : 24|8@1+ (1,0) [0|255] ""  PC
 SG_ S2P_Cfg11_HW_Ver_Byte13_38 : 32|8@1+ (1,0) [0|255] ""  PC
 SG_ S2P_Cfg11_HW_Ver_Byte14_38 : 40|8@1+ (1,0) [0|255] ""  PC
 SG_ S2P_Cfg11_HW_Ver_Byte15_38 : 48|8@1+ (1,0) [0|255] ""  PC
 SG_ S2P_Cfg11_HW_Ver_Byte16_38 : 56|8@1+ (1,0) [0|255] ""  PC

BO_ 2417749607 S2P_Cfg11__39: 8 SBMU
 SG_ S2P_Cfg11_HW_Ver_Byte9_39 : 0|8@1+ (1,0) [0|255] ""  PC
 SG_ S2P_Cfg11_HW_Ver_Byte10_39 : 8|8@1+ (1,0) [0|255] ""  PC
 SG_ S2P_Cfg11_HW_Ver_Byte11_39 : 16|8@1+ (1,0) [0|255] ""  PC
 SG_ S2P_Cfg11_HW_Ver_Byte12_39 : 24|8@1+ (1,0) [0|255] ""  PC
 SG_ S2P_Cfg11_HW_Ver_Byte13_39 : 32|8@1+ (1,0) [0|255] ""  PC
 SG_ S2P_Cfg11_HW_Ver_Byte14_39 : 40|8@1+ (1,0) [0|255] ""  PC
 SG_ S2P_Cfg11_HW_Ver_Byte15_39 : 48|8@1+ (1,0) [0|255] ""  PC
 SG_ S2P_Cfg11_HW_Ver_Byte16_39 : 56|8@1+ (1,0) [0|255] ""  PC

BO_ 2417749608 S2P_Cfg11__40: 8 SBMU
 SG_ S2P_Cfg11_HW_Ver_Byte9_40 : 0|8@1+ (1,0) [0|255] ""  PC
 SG_ S2P_Cfg11_HW_Ver_Byte10_40 : 8|8@1+ (1,0) [0|255] ""  PC
 SG_ S2P_Cfg11_HW_Ver_Byte11_40 : 16|8@1+ (1,0) [0|255] ""  PC
 SG_ S2P_Cfg11_HW_Ver_Byte12_40 : 24|8@1+ (1,0) [0|255] ""  PC
 SG_ S2P_Cfg11_HW_Ver_Byte13_40 : 32|8@1+ (1,0) [0|255] ""  PC
 SG_ S2P_Cfg11_HW_Ver_Byte14_40 : 40|8@1+ (1,0) [0|255] ""  PC
 SG_ S2P_Cfg11_HW_Ver_Byte15_40 : 48|8@1+ (1,0) [0|255] ""  PC
 SG_ S2P_Cfg11_HW_Ver_Byte16_40 : 56|8@1+ (1,0) [0|255] ""  PC

BO_ 2417749609 S2P_Cfg11__41: 8 SBMU
 SG_ S2P_Cfg11_HW_Ver_Byte9_41 : 0|8@1+ (1,0) [0|255] ""  PC
 SG_ S2P_Cfg11_HW_Ver_Byte10_41 : 8|8@1+ (1,0) [0|255] ""  PC
 SG_ S2P_Cfg11_HW_Ver_Byte11_41 : 16|8@1+ (1,0) [0|255] ""  PC
 SG_ S2P_Cfg11_HW_Ver_Byte12_41 : 24|8@1+ (1,0) [0|255] ""  PC
 SG_ S2P_Cfg11_HW_Ver_Byte13_41 : 32|8@1+ (1,0) [0|255] ""  PC
 SG_ S2P_Cfg11_HW_Ver_Byte14_41 : 40|8@1+ (1,0) [0|255] ""  PC
 SG_ S2P_Cfg11_HW_Ver_Byte15_41 : 48|8@1+ (1,0) [0|255] ""  PC
 SG_ S2P_Cfg11_HW_Ver_Byte16_41 : 56|8@1+ (1,0) [0|255] ""  PC

BO_ 2417749610 S2P_Cfg11__42: 8 SBMU
 SG_ S2P_Cfg11_HW_Ver_Byte9_42 : 0|8@1+ (1,0) [0|255] ""  PC
 SG_ S2P_Cfg11_HW_Ver_Byte10_42 : 8|8@1+ (1,0) [0|255] ""  PC
 SG_ S2P_Cfg11_HW_Ver_Byte11_42 : 16|8@1+ (1,0) [0|255] ""  PC
 SG_ S2P_Cfg11_HW_Ver_Byte12_42 : 24|8@1+ (1,0) [0|255] ""  PC
 SG_ S2P_Cfg11_HW_Ver_Byte13_42 : 32|8@1+ (1,0) [0|255] ""  PC
 SG_ S2P_Cfg11_HW_Ver_Byte14_42 : 40|8@1+ (1,0) [0|255] ""  PC
 SG_ S2P_Cfg11_HW_Ver_Byte15_42 : 48|8@1+ (1,0) [0|255] ""  PC
 SG_ S2P_Cfg11_HW_Ver_Byte16_42 : 56|8@1+ (1,0) [0|255] ""  PC

BO_ 2417749611 S2P_Cfg11__43: 8 SBMU
 SG_ S2P_Cfg11_HW_Ver_Byte9_43 : 0|8@1+ (1,0) [0|255] ""  PC
 SG_ S2P_Cfg11_HW_Ver_Byte10_43 : 8|8@1+ (1,0) [0|255] ""  PC
 SG_ S2P_Cfg11_HW_Ver_Byte11_43 : 16|8@1+ (1,0) [0|255] ""  PC
 SG_ S2P_Cfg11_HW_Ver_Byte12_43 : 24|8@1+ (1,0) [0|255] ""  PC
 SG_ S2P_Cfg11_HW_Ver_Byte13_43 : 32|8@1+ (1,0) [0|255] ""  PC
 SG_ S2P_Cfg11_HW_Ver_Byte14_43 : 40|8@1+ (1,0) [0|255] ""  PC
 SG_ S2P_Cfg11_HW_Ver_Byte15_43 : 48|8@1+ (1,0) [0|255] ""  PC
 SG_ S2P_Cfg11_HW_Ver_Byte16_43 : 56|8@1+ (1,0) [0|255] ""  PC

BO_ 2417749612 S2P_Cfg11__44: 8 SBMU
 SG_ S2P_Cfg11_HW_Ver_Byte9_44 : 0|8@1+ (1,0) [0|255] ""  PC
 SG_ S2P_Cfg11_HW_Ver_Byte10_44 : 8|8@1+ (1,0) [0|255] ""  PC
 SG_ S2P_Cfg11_HW_Ver_Byte11_44 : 16|8@1+ (1,0) [0|255] ""  PC
 SG_ S2P_Cfg11_HW_Ver_Byte12_44 : 24|8@1+ (1,0) [0|255] ""  PC
 SG_ S2P_Cfg11_HW_Ver_Byte13_44 : 32|8@1+ (1,0) [0|255] ""  PC
 SG_ S2P_Cfg11_HW_Ver_Byte14_44 : 40|8@1+ (1,0) [0|255] ""  PC
 SG_ S2P_Cfg11_HW_Ver_Byte15_44 : 48|8@1+ (1,0) [0|255] ""  PC
 SG_ S2P_Cfg11_HW_Ver_Byte16_44 : 56|8@1+ (1,0) [0|255] ""  PC

BO_ 2417749613 S2P_Cfg11__45: 8 SBMU
 SG_ S2P_Cfg11_HW_Ver_Byte9_45 : 0|8@1+ (1,0) [0|255] ""  PC
 SG_ S2P_Cfg11_HW_Ver_Byte10_45 : 8|8@1+ (1,0) [0|255] ""  PC
 SG_ S2P_Cfg11_HW_Ver_Byte11_45 : 16|8@1+ (1,0) [0|255] ""  PC
 SG_ S2P_Cfg11_HW_Ver_Byte12_45 : 24|8@1+ (1,0) [0|255] ""  PC
 SG_ S2P_Cfg11_HW_Ver_Byte13_45 : 32|8@1+ (1,0) [0|255] ""  PC
 SG_ S2P_Cfg11_HW_Ver_Byte14_45 : 40|8@1+ (1,0) [0|255] ""  PC
 SG_ S2P_Cfg11_HW_Ver_Byte15_45 : 48|8@1+ (1,0) [0|255] ""  PC
 SG_ S2P_Cfg11_HW_Ver_Byte16_45 : 56|8@1+ (1,0) [0|255] ""  PC

BO_ 2417749614 S2P_Cfg11__46: 8 SBMU
 SG_ S2P_Cfg11_HW_Ver_Byte9_46 : 0|8@1+ (1,0) [0|255] ""  PC
 SG_ S2P_Cfg11_HW_Ver_Byte10_46 : 8|8@1+ (1,0) [0|255] ""  PC
 SG_ S2P_Cfg11_HW_Ver_Byte11_46 : 16|8@1+ (1,0) [0|255] ""  PC
 SG_ S2P_Cfg11_HW_Ver_Byte12_46 : 24|8@1+ (1,0) [0|255] ""  PC
 SG_ S2P_Cfg11_HW_Ver_Byte13_46 : 32|8@1+ (1,0) [0|255] ""  PC
 SG_ S2P_Cfg11_HW_Ver_Byte14_46 : 40|8@1+ (1,0) [0|255] ""  PC
 SG_ S2P_Cfg11_HW_Ver_Byte15_46 : 48|8@1+ (1,0) [0|255] ""  PC
 SG_ S2P_Cfg11_HW_Ver_Byte16_46 : 56|8@1+ (1,0) [0|255] ""  PC

BO_ 2417749615 S2P_Cfg11__47: 8 SBMU
 SG_ S2P_Cfg11_HW_Ver_Byte9_47 : 0|8@1+ (1,0) [0|255] ""  PC
 SG_ S2P_Cfg11_HW_Ver_Byte10_47 : 8|8@1+ (1,0) [0|255] ""  PC
 SG_ S2P_Cfg11_HW_Ver_Byte11_47 : 16|8@1+ (1,0) [0|255] ""  PC
 SG_ S2P_Cfg11_HW_Ver_Byte12_47 : 24|8@1+ (1,0) [0|255] ""  PC
 SG_ S2P_Cfg11_HW_Ver_Byte13_47 : 32|8@1+ (1,0) [0|255] ""  PC
 SG_ S2P_Cfg11_HW_Ver_Byte14_47 : 40|8@1+ (1,0) [0|255] ""  PC
 SG_ S2P_Cfg11_HW_Ver_Byte15_47 : 48|8@1+ (1,0) [0|255] ""  PC
 SG_ S2P_Cfg11_HW_Ver_Byte16_47 : 56|8@1+ (1,0) [0|255] ""  PC

BO_ 2417749616 S2P_Cfg11__48: 8 SBMU
 SG_ S2P_Cfg11_HW_Ver_Byte9_48 : 0|8@1+ (1,0) [0|255] ""  PC
 SG_ S2P_Cfg11_HW_Ver_Byte10_48 : 8|8@1+ (1,0) [0|255] ""  PC
 SG_ S2P_Cfg11_HW_Ver_Byte11_48 : 16|8@1+ (1,0) [0|255] ""  PC
 SG_ S2P_Cfg11_HW_Ver_Byte12_48 : 24|8@1+ (1,0) [0|255] ""  PC
 SG_ S2P_Cfg11_HW_Ver_Byte13_48 : 32|8@1+ (1,0) [0|255] ""  PC
 SG_ S2P_Cfg11_HW_Ver_Byte14_48 : 40|8@1+ (1,0) [0|255] ""  PC
 SG_ S2P_Cfg11_HW_Ver_Byte15_48 : 48|8@1+ (1,0) [0|255] ""  PC
 SG_ S2P_Cfg11_HW_Ver_Byte16_48 : 56|8@1+ (1,0) [0|255] ""  PC

BO_ 2417749617 S2P_Cfg11__49: 8 SBMU
 SG_ S2P_Cfg11_HW_Ver_Byte9_49 : 0|8@1+ (1,0) [0|255] ""  PC
 SG_ S2P_Cfg11_HW_Ver_Byte10_49 : 8|8@1+ (1,0) [0|255] ""  PC
 SG_ S2P_Cfg11_HW_Ver_Byte11_49 : 16|8@1+ (1,0) [0|255] ""  PC
 SG_ S2P_Cfg11_HW_Ver_Byte12_49 : 24|8@1+ (1,0) [0|255] ""  PC
 SG_ S2P_Cfg11_HW_Ver_Byte13_49 : 32|8@1+ (1,0) [0|255] ""  PC
 SG_ S2P_Cfg11_HW_Ver_Byte14_49 : 40|8@1+ (1,0) [0|255] ""  PC
 SG_ S2P_Cfg11_HW_Ver_Byte15_49 : 48|8@1+ (1,0) [0|255] ""  PC
 SG_ S2P_Cfg11_HW_Ver_Byte16_49 : 56|8@1+ (1,0) [0|255] ""  PC

BO_ 2417749618 S2P_Cfg11__50: 8 SBMU
 SG_ S2P_Cfg11_HW_Ver_Byte9_50 : 0|8@1+ (1,0) [0|255] ""  PC
 SG_ S2P_Cfg11_HW_Ver_Byte10_50 : 8|8@1+ (1,0) [0|255] ""  PC
 SG_ S2P_Cfg11_HW_Ver_Byte11_50 : 16|8@1+ (1,0) [0|255] ""  PC
 SG_ S2P_Cfg11_HW_Ver_Byte12_50 : 24|8@1+ (1,0) [0|255] ""  PC
 SG_ S2P_Cfg11_HW_Ver_Byte13_50 : 32|8@1+ (1,0) [0|255] ""  PC
 SG_ S2P_Cfg11_HW_Ver_Byte14_50 : 40|8@1+ (1,0) [0|255] ""  PC
 SG_ S2P_Cfg11_HW_Ver_Byte15_50 : 48|8@1+ (1,0) [0|255] ""  PC
 SG_ S2P_Cfg11_HW_Ver_Byte16_50 : 56|8@1+ (1,0) [0|255] ""  PC

BO_ 2417749619 S2P_Cfg11__51: 8 SBMU
 SG_ S2P_Cfg11_HW_Ver_Byte9_51 : 0|8@1+ (1,0) [0|255] ""  PC
 SG_ S2P_Cfg11_HW_Ver_Byte10_51 : 8|8@1+ (1,0) [0|255] ""  PC
 SG_ S2P_Cfg11_HW_Ver_Byte11_51 : 16|8@1+ (1,0) [0|255] ""  PC
 SG_ S2P_Cfg11_HW_Ver_Byte12_51 : 24|8@1+ (1,0) [0|255] ""  PC
 SG_ S2P_Cfg11_HW_Ver_Byte13_51 : 32|8@1+ (1,0) [0|255] ""  PC
 SG_ S2P_Cfg11_HW_Ver_Byte14_51 : 40|8@1+ (1,0) [0|255] ""  PC
 SG_ S2P_Cfg11_HW_Ver_Byte15_51 : 48|8@1+ (1,0) [0|255] ""  PC
 SG_ S2P_Cfg11_HW_Ver_Byte16_51 : 56|8@1+ (1,0) [0|255] ""  PC

BO_ 2417749620 S2P_Cfg11__52: 8 SBMU
 SG_ S2P_Cfg11_HW_Ver_Byte9_52 : 0|8@1+ (1,0) [0|255] ""  PC
 SG_ S2P_Cfg11_HW_Ver_Byte10_52 : 8|8@1+ (1,0) [0|255] ""  PC
 SG_ S2P_Cfg11_HW_Ver_Byte11_52 : 16|8@1+ (1,0) [0|255] ""  PC
 SG_ S2P_Cfg11_HW_Ver_Byte12_52 : 24|8@1+ (1,0) [0|255] ""  PC
 SG_ S2P_Cfg11_HW_Ver_Byte13_52 : 32|8@1+ (1,0) [0|255] ""  PC
 SG_ S2P_Cfg11_HW_Ver_Byte14_52 : 40|8@1+ (1,0) [0|255] ""  PC
 SG_ S2P_Cfg11_HW_Ver_Byte15_52 : 48|8@1+ (1,0) [0|255] ""  PC
 SG_ S2P_Cfg11_HW_Ver_Byte16_52 : 56|8@1+ (1,0) [0|255] ""  PC

BO_ 2417749621 S2P_Cfg11__53: 8 SBMU
 SG_ S2P_Cfg11_HW_Ver_Byte9_53 : 0|8@1+ (1,0) [0|255] ""  PC
 SG_ S2P_Cfg11_HW_Ver_Byte10_53 : 8|8@1+ (1,0) [0|255] ""  PC
 SG_ S2P_Cfg11_HW_Ver_Byte11_53 : 16|8@1+ (1,0) [0|255] ""  PC
 SG_ S2P_Cfg11_HW_Ver_Byte12_53 : 24|8@1+ (1,0) [0|255] ""  PC
 SG_ S2P_Cfg11_HW_Ver_Byte13_53 : 32|8@1+ (1,0) [0|255] ""  PC
 SG_ S2P_Cfg11_HW_Ver_Byte14_53 : 40|8@1+ (1,0) [0|255] ""  PC
 SG_ S2P_Cfg11_HW_Ver_Byte15_53 : 48|8@1+ (1,0) [0|255] ""  PC
 SG_ S2P_Cfg11_HW_Ver_Byte16_53 : 56|8@1+ (1,0) [0|255] ""  PC

BO_ 2417749622 S2P_Cfg11__54: 8 SBMU
 SG_ S2P_Cfg11_HW_Ver_Byte9_54 : 0|8@1+ (1,0) [0|255] ""  PC
 SG_ S2P_Cfg11_HW_Ver_Byte10_54 : 8|8@1+ (1,0) [0|255] ""  PC
 SG_ S2P_Cfg11_HW_Ver_Byte11_54 : 16|8@1+ (1,0) [0|255] ""  PC
 SG_ S2P_Cfg11_HW_Ver_Byte12_54 : 24|8@1+ (1,0) [0|255] ""  PC
 SG_ S2P_Cfg11_HW_Ver_Byte13_54 : 32|8@1+ (1,0) [0|255] ""  PC
 SG_ S2P_Cfg11_HW_Ver_Byte14_54 : 40|8@1+ (1,0) [0|255] ""  PC
 SG_ S2P_Cfg11_HW_Ver_Byte15_54 : 48|8@1+ (1,0) [0|255] ""  PC
 SG_ S2P_Cfg11_HW_Ver_Byte16_54 : 56|8@1+ (1,0) [0|255] ""  PC

BO_ 2417749623 S2P_Cfg11__55: 8 SBMU
 SG_ S2P_Cfg11_HW_Ver_Byte9_55 : 0|8@1+ (1,0) [0|255] ""  PC
 SG_ S2P_Cfg11_HW_Ver_Byte10_55 : 8|8@1+ (1,0) [0|255] ""  PC
 SG_ S2P_Cfg11_HW_Ver_Byte11_55 : 16|8@1+ (1,0) [0|255] ""  PC
 SG_ S2P_Cfg11_HW_Ver_Byte12_55 : 24|8@1+ (1,0) [0|255] ""  PC
 SG_ S2P_Cfg11_HW_Ver_Byte13_55 : 32|8@1+ (1,0) [0|255] ""  PC
 SG_ S2P_Cfg11_HW_Ver_Byte14_55 : 40|8@1+ (1,0) [0|255] ""  PC
 SG_ S2P_Cfg11_HW_Ver_Byte15_55 : 48|8@1+ (1,0) [0|255] ""  PC
 SG_ S2P_Cfg11_HW_Ver_Byte16_55 : 56|8@1+ (1,0) [0|255] ""  PC

BO_ 2417749624 S2P_Cfg11__56: 8 SBMU
 SG_ S2P_Cfg11_HW_Ver_Byte9_56 : 0|8@1+ (1,0) [0|255] ""  PC
 SG_ S2P_Cfg11_HW_Ver_Byte10_56 : 8|8@1+ (1,0) [0|255] ""  PC
 SG_ S2P_Cfg11_HW_Ver_Byte11_56 : 16|8@1+ (1,0) [0|255] ""  PC
 SG_ S2P_Cfg11_HW_Ver_Byte12_56 : 24|8@1+ (1,0) [0|255] ""  PC
 SG_ S2P_Cfg11_HW_Ver_Byte13_56 : 32|8@1+ (1,0) [0|255] ""  PC
 SG_ S2P_Cfg11_HW_Ver_Byte14_56 : 40|8@1+ (1,0) [0|255] ""  PC
 SG_ S2P_Cfg11_HW_Ver_Byte15_56 : 48|8@1+ (1,0) [0|255] ""  PC
 SG_ S2P_Cfg11_HW_Ver_Byte16_56 : 56|8@1+ (1,0) [0|255] ""  PC

BO_ 2417749625 S2P_Cfg11__57: 8 SBMU
 SG_ S2P_Cfg11_HW_Ver_Byte9_57 : 0|8@1+ (1,0) [0|255] ""  PC
 SG_ S2P_Cfg11_HW_Ver_Byte10_57 : 8|8@1+ (1,0) [0|255] ""  PC
 SG_ S2P_Cfg11_HW_Ver_Byte11_57 : 16|8@1+ (1,0) [0|255] ""  PC
 SG_ S2P_Cfg11_HW_Ver_Byte12_57 : 24|8@1+ (1,0) [0|255] ""  PC
 SG_ S2P_Cfg11_HW_Ver_Byte13_57 : 32|8@1+ (1,0) [0|255] ""  PC
 SG_ S2P_Cfg11_HW_Ver_Byte14_57 : 40|8@1+ (1,0) [0|255] ""  PC
 SG_ S2P_Cfg11_HW_Ver_Byte15_57 : 48|8@1+ (1,0) [0|255] ""  PC
 SG_ S2P_Cfg11_HW_Ver_Byte16_57 : 56|8@1+ (1,0) [0|255] ""  PC

BO_ 2417749626 S2P_Cfg11__58: 8 SBMU
 SG_ S2P_Cfg11_HW_Ver_Byte9_58 : 0|8@1+ (1,0) [0|255] ""  PC
 SG_ S2P_Cfg11_HW_Ver_Byte10_58 : 8|8@1+ (1,0) [0|255] ""  PC
 SG_ S2P_Cfg11_HW_Ver_Byte11_58 : 16|8@1+ (1,0) [0|255] ""  PC
 SG_ S2P_Cfg11_HW_Ver_Byte12_58 : 24|8@1+ (1,0) [0|255] ""  PC
 SG_ S2P_Cfg11_HW_Ver_Byte13_58 : 32|8@1+ (1,0) [0|255] ""  PC
 SG_ S2P_Cfg11_HW_Ver_Byte14_58 : 40|8@1+ (1,0) [0|255] ""  PC
 SG_ S2P_Cfg11_HW_Ver_Byte15_58 : 48|8@1+ (1,0) [0|255] ""  PC
 SG_ S2P_Cfg11_HW_Ver_Byte16_58 : 56|8@1+ (1,0) [0|255] ""  PC

BO_ 2417749627 S2P_Cfg11__59: 8 SBMU
 SG_ S2P_Cfg11_HW_Ver_Byte9_59 : 0|8@1+ (1,0) [0|255] ""  PC
 SG_ S2P_Cfg11_HW_Ver_Byte10_59 : 8|8@1+ (1,0) [0|255] ""  PC
 SG_ S2P_Cfg11_HW_Ver_Byte11_59 : 16|8@1+ (1,0) [0|255] ""  PC
 SG_ S2P_Cfg11_HW_Ver_Byte12_59 : 24|8@1+ (1,0) [0|255] ""  PC
 SG_ S2P_Cfg11_HW_Ver_Byte13_59 : 32|8@1+ (1,0) [0|255] ""  PC
 SG_ S2P_Cfg11_HW_Ver_Byte14_59 : 40|8@1+ (1,0) [0|255] ""  PC
 SG_ S2P_Cfg11_HW_Ver_Byte15_59 : 48|8@1+ (1,0) [0|255] ""  PC
 SG_ S2P_Cfg11_HW_Ver_Byte16_59 : 56|8@1+ (1,0) [0|255] ""  PC

BO_ 2417749628 S2P_Cfg11__60: 8 SBMU
 SG_ S2P_Cfg11_HW_Ver_Byte9_60 : 0|8@1+ (1,0) [0|255] ""  PC
 SG_ S2P_Cfg11_HW_Ver_Byte10_60 : 8|8@1+ (1,0) [0|255] ""  PC
 SG_ S2P_Cfg11_HW_Ver_Byte11_60 : 16|8@1+ (1,0) [0|255] ""  PC
 SG_ S2P_Cfg11_HW_Ver_Byte12_60 : 24|8@1+ (1,0) [0|255] ""  PC
 SG_ S2P_Cfg11_HW_Ver_Byte13_60 : 32|8@1+ (1,0) [0|255] ""  PC
 SG_ S2P_Cfg11_HW_Ver_Byte14_60 : 40|8@1+ (1,0) [0|255] ""  PC
 SG_ S2P_Cfg11_HW_Ver_Byte15_60 : 48|8@1+ (1,0) [0|255] ""  PC
 SG_ S2P_Cfg11_HW_Ver_Byte16_60 : 56|8@1+ (1,0) [0|255] ""  PC

CM_ SG_ 2417618518 S2P_Cfg9_SW_Ver_Byte9_22 "CSC软件版本号Byte9对应的ASCII码";
CM_ SG_ 2417618518 S2P_Cfg9_SW_Ver_Byte10_22 "CSC软件版本号Byte10对应的ASCII码";
CM_ SG_ 2417618518 S2P_Cfg9_SW_Ver_Byte11_22 "CSC软件版本号Byte11对应的ASCII码";
CM_ SG_ 2417618518 S2P_Cfg9_SW_Ver_Byte12_22 "CSC软件版本号Byte12对应的ASCII码";
CM_ SG_ 2417618518 S2P_Cfg9_SW_Ver_Byte13_22 "CSC软件版本号Byte13对应的ASCII码";
CM_ SG_ 2417618518 S2P_Cfg9_SW_Ver_Byte14_22 "CSC软件版本号Byte14对应的ASCII码";
CM_ SG_ 2417618518 S2P_Cfg9_SW_Ver_Byte15_22 "CSC软件版本号Byte15对应的ASCII码";
CM_ SG_ 2417618518 S2P_Cfg9_SW_Ver_Byte16_22 "CSC软件版本号最高字节Byte16对应的ASCII码";
CM_ SG_ 2417618519 S2P_Cfg9_SW_Ver_Byte9_23 "CSC软件版本号Byte9对应的ASCII码";
CM_ SG_ 2417618519 S2P_Cfg9_SW_Ver_Byte10_23 "CSC软件版本号Byte10对应的ASCII码";
CM_ SG_ 2417618519 S2P_Cfg9_SW_Ver_Byte11_23 "CSC软件版本号Byte11对应的ASCII码";
CM_ SG_ 2417618519 S2P_Cfg9_SW_Ver_Byte12_23 "CSC软件版本号Byte12对应的ASCII码";
CM_ SG_ 2417618519 S2P_Cfg9_SW_Ver_Byte13_23 "CSC软件版本号Byte13对应的ASCII码";
CM_ SG_ 2417618519 S2P_Cfg9_SW_Ver_Byte14_23 "CSC软件版本号Byte14对应的ASCII码";
CM_ SG_ 2417618519 S2P_Cfg9_SW_Ver_Byte15_23 "CSC软件版本号Byte15对应的ASCII码";
CM_ SG_ 2417618519 S2P_Cfg9_SW_Ver_Byte16_23 "CSC软件版本号最高字节Byte16对应的ASCII码";
CM_ SG_ 2417618520 S2P_Cfg9_SW_Ver_Byte9_24 "CSC软件版本号Byte9对应的ASCII码";
CM_ SG_ 2417618520 S2P_Cfg9_SW_Ver_Byte10_24 "CSC软件版本号Byte10对应的ASCII码";
CM_ SG_ 2417618520 S2P_Cfg9_SW_Ver_Byte11_24 "CSC软件版本号Byte11对应的ASCII码";
CM_ SG_ 2417618520 S2P_Cfg9_SW_Ver_Byte12_24 "CSC软件版本号Byte12对应的ASCII码";
CM_ SG_ 2417618520 S2P_Cfg9_SW_Ver_Byte13_24 "CSC软件版本号Byte13对应的ASCII码";
CM_ SG_ 2417618520 S2P_Cfg9_SW_Ver_Byte14_24 "CSC软件版本号Byte14对应的ASCII码";
CM_ SG_ 2417618520 S2P_Cfg9_SW_Ver_Byte15_24 "CSC软件版本号Byte15对应的ASCII码";
CM_ SG_ 2417618520 S2P_Cfg9_SW_Ver_Byte16_24 "CSC软件版本号最高字节Byte16对应的ASCII码";
CM_ SG_ 2417618521 S2P_Cfg9_SW_Ver_Byte9_25 "CSC软件版本号Byte9对应的ASCII码";
CM_ SG_ 2417618521 S2P_Cfg9_SW_Ver_Byte10_25 "CSC软件版本号Byte10对应的ASCII码";
CM_ SG_ 2417618521 S2P_Cfg9_SW_Ver_Byte11_25 "CSC软件版本号Byte11对应的ASCII码";
CM_ SG_ 2417618521 S2P_Cfg9_SW_Ver_Byte12_25 "CSC软件版本号Byte12对应的ASCII码";
CM_ SG_ 2417618521 S2P_Cfg9_SW_Ver_Byte13_25 "CSC软件版本号Byte13对应的ASCII码";
CM_ SG_ 2417618521 S2P_Cfg9_SW_Ver_Byte14_25 "CSC软件版本号Byte14对应的ASCII码";
CM_ SG_ 2417618521 S2P_Cfg9_SW_Ver_Byte15_25 "CSC软件版本号Byte15对应的ASCII码";
CM_ SG_ 2417618521 S2P_Cfg9_SW_Ver_Byte16_25 "CSC软件版本号最高字节Byte16对应的ASCII码";
CM_ SG_ 2417618522 S2P_Cfg9_SW_Ver_Byte9_26 "CSC软件版本号Byte9对应的ASCII码";
CM_ SG_ 2417618522 S2P_Cfg9_SW_Ver_Byte10_26 "CSC软件版本号Byte10对应的ASCII码";
CM_ SG_ 2417618522 S2P_Cfg9_SW_Ver_Byte11_26 "CSC软件版本号Byte11对应的ASCII码";
CM_ SG_ 2417618522 S2P_Cfg9_SW_Ver_Byte12_26 "CSC软件版本号Byte12对应的ASCII码";
CM_ SG_ 2417618522 S2P_Cfg9_SW_Ver_Byte13_26 "CSC软件版本号Byte13对应的ASCII码";
CM_ SG_ 2417618522 S2P_Cfg9_SW_Ver_Byte14_26 "CSC软件版本号Byte14对应的ASCII码";
CM_ SG_ 2417618522 S2P_Cfg9_SW_Ver_Byte15_26 "CSC软件版本号Byte15对应的ASCII码";
CM_ SG_ 2417618522 S2P_Cfg9_SW_Ver_Byte16_26 "CSC软件版本号最高字节Byte16对应的ASCII码";
CM_ SG_ 2417618523 S2P_Cfg9_SW_Ver_Byte9_27 "CSC软件版本号Byte9对应的ASCII码";
CM_ SG_ 2417618523 S2P_Cfg9_SW_Ver_Byte10_27 "CSC软件版本号Byte10对应的ASCII码";
CM_ SG_ 2417618523 S2P_Cfg9_SW_Ver_Byte11_27 "CSC软件版本号Byte11对应的ASCII码";
CM_ SG_ 2417618523 S2P_Cfg9_SW_Ver_Byte12_27 "CSC软件版本号Byte12对应的ASCII码";
CM_ SG_ 2417618523 S2P_Cfg9_SW_Ver_Byte13_27 "CSC软件版本号Byte13对应的ASCII码";
CM_ SG_ 2417618523 S2P_Cfg9_SW_Ver_Byte14_27 "CSC软件版本号Byte14对应的ASCII码";
CM_ SG_ 2417618523 S2P_Cfg9_SW_Ver_Byte15_27 "CSC软件版本号Byte15对应的ASCII码";
CM_ SG_ 2417618523 S2P_Cfg9_SW_Ver_Byte16_27 "CSC软件版本号最高字节Byte16对应的ASCII码";
CM_ SG_ 2417618524 S2P_Cfg9_SW_Ver_Byte9_28 "CSC软件版本号Byte9对应的ASCII码";
CM_ SG_ 2417618524 S2P_Cfg9_SW_Ver_Byte10_28 "CSC软件版本号Byte10对应的ASCII码";
CM_ SG_ 2417618524 S2P_Cfg9_SW_Ver_Byte11_28 "CSC软件版本号Byte11对应的ASCII码";
CM_ SG_ 2417618524 S2P_Cfg9_SW_Ver_Byte12_28 "CSC软件版本号Byte12对应的ASCII码";
CM_ SG_ 2417618524 S2P_Cfg9_SW_Ver_Byte13_28 "CSC软件版本号Byte13对应的ASCII码";
CM_ SG_ 2417618524 S2P_Cfg9_SW_Ver_Byte14_28 "CSC软件版本号Byte14对应的ASCII码";
CM_ SG_ 2417618524 S2P_Cfg9_SW_Ver_Byte15_28 "CSC软件版本号Byte15对应的ASCII码";
CM_ SG_ 2417618524 S2P_Cfg9_SW_Ver_Byte16_28 "CSC软件版本号最高字节Byte16对应的ASCII码";
CM_ SG_ 2417618525 S2P_Cfg9_SW_Ver_Byte9_29 "CSC软件版本号Byte9对应的ASCII码";
CM_ SG_ 2417618525 S2P_Cfg9_SW_Ver_Byte10_29 "CSC软件版本号Byte10对应的ASCII码";
CM_ SG_ 2417618525 S2P_Cfg9_SW_Ver_Byte11_29 "CSC软件版本号Byte11对应的ASCII码";
CM_ SG_ 2417618525 S2P_Cfg9_SW_Ver_Byte12_29 "CSC软件版本号Byte12对应的ASCII码";
CM_ SG_ 2417618525 S2P_Cfg9_SW_Ver_Byte13_29 "CSC软件版本号Byte13对应的ASCII码";
CM_ SG_ 2417618525 S2P_Cfg9_SW_Ver_Byte14_29 "CSC软件版本号Byte14对应的ASCII码";
CM_ SG_ 2417618525 S2P_Cfg9_SW_Ver_Byte15_29 "CSC软件版本号Byte15对应的ASCII码";
CM_ SG_ 2417618525 S2P_Cfg9_SW_Ver_Byte16_29 "CSC软件版本号最高字节Byte16对应的ASCII码";
CM_ SG_ 2417618526 S2P_Cfg9_SW_Ver_Byte9_30 "CSC软件版本号Byte9对应的ASCII码";
CM_ SG_ 2417618526 S2P_Cfg9_SW_Ver_Byte10_30 "CSC软件版本号Byte10对应的ASCII码";
CM_ SG_ 2417618526 S2P_Cfg9_SW_Ver_Byte11_30 "CSC软件版本号Byte11对应的ASCII码";
CM_ SG_ 2417618526 S2P_Cfg9_SW_Ver_Byte12_30 "CSC软件版本号Byte12对应的ASCII码";
CM_ SG_ 2417618526 S2P_Cfg9_SW_Ver_Byte13_30 "CSC软件版本号Byte13对应的ASCII码";
CM_ SG_ 2417618526 S2P_Cfg9_SW_Ver_Byte14_30 "CSC软件版本号Byte14对应的ASCII码";
CM_ SG_ 2417618526 S2P_Cfg9_SW_Ver_Byte15_30 "CSC软件版本号Byte15对应的ASCII码";
CM_ SG_ 2417618526 S2P_Cfg9_SW_Ver_Byte16_30 "CSC软件版本号最高字节Byte16对应的ASCII码";
CM_ SG_ 2417618527 S2P_Cfg9_SW_Ver_Byte9_31 "CSC软件版本号Byte9对应的ASCII码";
CM_ SG_ 2417618527 S2P_Cfg9_SW_Ver_Byte10_31 "CSC软件版本号Byte10对应的ASCII码";
CM_ SG_ 2417618527 S2P_Cfg9_SW_Ver_Byte11_31 "CSC软件版本号Byte11对应的ASCII码";
CM_ SG_ 2417618527 S2P_Cfg9_SW_Ver_Byte12_31 "CSC软件版本号Byte12对应的ASCII码";
CM_ SG_ 2417618527 S2P_Cfg9_SW_Ver_Byte13_31 "CSC软件版本号Byte13对应的ASCII码";
CM_ SG_ 2417618527 S2P_Cfg9_SW_Ver_Byte14_31 "CSC软件版本号Byte14对应的ASCII码";
CM_ SG_ 2417618527 S2P_Cfg9_SW_Ver_Byte15_31 "CSC软件版本号Byte15对应的ASCII码";
CM_ SG_ 2417618527 S2P_Cfg9_SW_Ver_Byte16_31 "CSC软件版本号最高字节Byte16对应的ASCII码";
CM_ SG_ 2417618528 S2P_Cfg9_SW_Ver_Byte9_32 "CSC软件版本号Byte9对应的ASCII码";
CM_ SG_ 2417618528 S2P_Cfg9_SW_Ver_Byte10_32 "CSC软件版本号Byte10对应的ASCII码";
CM_ SG_ 2417618528 S2P_Cfg9_SW_Ver_Byte11_32 "CSC软件版本号Byte11对应的ASCII码";
CM_ SG_ 2417618528 S2P_Cfg9_SW_Ver_Byte12_32 "CSC软件版本号Byte12对应的ASCII码";
CM_ SG_ 2417618528 S2P_Cfg9_SW_Ver_Byte13_32 "CSC软件版本号Byte13对应的ASCII码";
CM_ SG_ 2417618528 S2P_Cfg9_SW_Ver_Byte14_32 "CSC软件版本号Byte14对应的ASCII码";
CM_ SG_ 2417618528 S2P_Cfg9_SW_Ver_Byte15_32 "CSC软件版本号Byte15对应的ASCII码";
CM_ SG_ 2417618528 S2P_Cfg9_SW_Ver_Byte16_32 "CSC软件版本号最高字节Byte16对应的ASCII码";
CM_ SG_ 2417618529 S2P_Cfg9_SW_Ver_Byte9_33 "CSC软件版本号Byte9对应的ASCII码";
CM_ SG_ 2417618529 S2P_Cfg9_SW_Ver_Byte10_33 "CSC软件版本号Byte10对应的ASCII码";
CM_ SG_ 2417618529 S2P_Cfg9_SW_Ver_Byte11_33 "CSC软件版本号Byte11对应的ASCII码";
CM_ SG_ 2417618529 S2P_Cfg9_SW_Ver_Byte12_33 "CSC软件版本号Byte12对应的ASCII码";
CM_ SG_ 2417618529 S2P_Cfg9_SW_Ver_Byte13_33 "CSC软件版本号Byte13对应的ASCII码";
CM_ SG_ 2417618529 S2P_Cfg9_SW_Ver_Byte14_33 "CSC软件版本号Byte14对应的ASCII码";
CM_ SG_ 2417618529 S2P_Cfg9_SW_Ver_Byte15_33 "CSC软件版本号Byte15对应的ASCII码";
CM_ SG_ 2417618529 S2P_Cfg9_SW_Ver_Byte16_33 "CSC软件版本号最高字节Byte16对应的ASCII码";
CM_ SG_ 2417618530 S2P_Cfg9_SW_Ver_Byte9_34 "CSC软件版本号Byte9对应的ASCII码";
CM_ SG_ 2417618530 S2P_Cfg9_SW_Ver_Byte10_34 "CSC软件版本号Byte10对应的ASCII码";
CM_ SG_ 2417618530 S2P_Cfg9_SW_Ver_Byte11_34 "CSC软件版本号Byte11对应的ASCII码";
CM_ SG_ 2417618530 S2P_Cfg9_SW_Ver_Byte12_34 "CSC软件版本号Byte12对应的ASCII码";
CM_ SG_ 2417618530 S2P_Cfg9_SW_Ver_Byte13_34 "CSC软件版本号Byte13对应的ASCII码";
CM_ SG_ 2417618530 S2P_Cfg9_SW_Ver_Byte14_34 "CSC软件版本号Byte14对应的ASCII码";
CM_ SG_ 2417618530 S2P_Cfg9_SW_Ver_Byte15_34 "CSC软件版本号Byte15对应的ASCII码";
CM_ SG_ 2417618530 S2P_Cfg9_SW_Ver_Byte16_34 "CSC软件版本号最高字节Byte16对应的ASCII码";
CM_ SG_ 2417618531 S2P_Cfg9_SW_Ver_Byte9_35 "CSC软件版本号Byte9对应的ASCII码";
CM_ SG_ 2417618531 S2P_Cfg9_SW_Ver_Byte10_35 "CSC软件版本号Byte10对应的ASCII码";
CM_ SG_ 2417618531 S2P_Cfg9_SW_Ver_Byte11_35 "CSC软件版本号Byte11对应的ASCII码";
CM_ SG_ 2417618531 S2P_Cfg9_SW_Ver_Byte12_35 "CSC软件版本号Byte12对应的ASCII码";
CM_ SG_ 2417618531 S2P_Cfg9_SW_Ver_Byte13_35 "CSC软件版本号Byte13对应的ASCII码";
CM_ SG_ 2417618531 S2P_Cfg9_SW_Ver_Byte14_35 "CSC软件版本号Byte14对应的ASCII码";
CM_ SG_ 2417618531 S2P_Cfg9_SW_Ver_Byte15_35 "CSC软件版本号Byte15对应的ASCII码";
CM_ SG_ 2417618531 S2P_Cfg9_SW_Ver_Byte16_35 "CSC软件版本号最高字节Byte16对应的ASCII码";
CM_ SG_ 2417618532 S2P_Cfg9_SW_Ver_Byte9_36 "CSC软件版本号Byte9对应的ASCII码";
CM_ SG_ 2417618532 S2P_Cfg9_SW_Ver_Byte10_36 "CSC软件版本号Byte10对应的ASCII码";
CM_ SG_ 2417618532 S2P_Cfg9_SW_Ver_Byte11_36 "CSC软件版本号Byte11对应的ASCII码";
CM_ SG_ 2417618532 S2P_Cfg9_SW_Ver_Byte12_36 "CSC软件版本号Byte12对应的ASCII码";
CM_ SG_ 2417618532 S2P_Cfg9_SW_Ver_Byte13_36 "CSC软件版本号Byte13对应的ASCII码";
CM_ SG_ 2417618532 S2P_Cfg9_SW_Ver_Byte14_36 "CSC软件版本号Byte14对应的ASCII码";
CM_ SG_ 2417618532 S2P_Cfg9_SW_Ver_Byte15_36 "CSC软件版本号Byte15对应的ASCII码";
CM_ SG_ 2417618532 S2P_Cfg9_SW_Ver_Byte16_36 "CSC软件版本号最高字节Byte16对应的ASCII码";
CM_ SG_ 2417618533 S2P_Cfg9_SW_Ver_Byte9_37 "CSC软件版本号Byte9对应的ASCII码";
CM_ SG_ 2417618533 S2P_Cfg9_SW_Ver_Byte10_37 "CSC软件版本号Byte10对应的ASCII码";
CM_ SG_ 2417618533 S2P_Cfg9_SW_Ver_Byte11_37 "CSC软件版本号Byte11对应的ASCII码";
CM_ SG_ 2417618533 S2P_Cfg9_SW_Ver_Byte12_37 "CSC软件版本号Byte12对应的ASCII码";
CM_ SG_ 2417618533 S2P_Cfg9_SW_Ver_Byte13_37 "CSC软件版本号Byte13对应的ASCII码";
CM_ SG_ 2417618533 S2P_Cfg9_SW_Ver_Byte14_37 "CSC软件版本号Byte14对应的ASCII码";
CM_ SG_ 2417618533 S2P_Cfg9_SW_Ver_Byte15_37 "CSC软件版本号Byte15对应的ASCII码";
CM_ SG_ 2417618533 S2P_Cfg9_SW_Ver_Byte16_37 "CSC软件版本号最高字节Byte16对应的ASCII码";
CM_ SG_ 2417618534 S2P_Cfg9_SW_Ver_Byte9_38 "CSC软件版本号Byte9对应的ASCII码";
CM_ SG_ 2417618534 S2P_Cfg9_SW_Ver_Byte10_38 "CSC软件版本号Byte10对应的ASCII码";
CM_ SG_ 2417618534 S2P_Cfg9_SW_Ver_Byte11_38 "CSC软件版本号Byte11对应的ASCII码";
CM_ SG_ 2417618534 S2P_Cfg9_SW_Ver_Byte12_38 "CSC软件版本号Byte12对应的ASCII码";
CM_ SG_ 2417618534 S2P_Cfg9_SW_Ver_Byte13_38 "CSC软件版本号Byte13对应的ASCII码";
CM_ SG_ 2417618534 S2P_Cfg9_SW_Ver_Byte14_38 "CSC软件版本号Byte14对应的ASCII码";
CM_ SG_ 2417618534 S2P_Cfg9_SW_Ver_Byte15_38 "CSC软件版本号Byte15对应的ASCII码";
CM_ SG_ 2417618534 S2P_Cfg9_SW_Ver_Byte16_38 "CSC软件版本号最高字节Byte16对应的ASCII码";
CM_ SG_ 2417618535 S2P_Cfg9_SW_Ver_Byte9_39 "CSC软件版本号Byte9对应的ASCII码";
CM_ SG_ 2417618535 S2P_Cfg9_SW_Ver_Byte10_39 "CSC软件版本号Byte10对应的ASCII码";
CM_ SG_ 2417618535 S2P_Cfg9_SW_Ver_Byte11_39 "CSC软件版本号Byte11对应的ASCII码";
CM_ SG_ 2417618535 S2P_Cfg9_SW_Ver_Byte12_39 "CSC软件版本号Byte12对应的ASCII码";
CM_ SG_ 2417618535 S2P_Cfg9_SW_Ver_Byte13_39 "CSC软件版本号Byte13对应的ASCII码";
CM_ SG_ 2417618535 S2P_Cfg9_SW_Ver_Byte14_39 "CSC软件版本号Byte14对应的ASCII码";
CM_ SG_ 2417618535 S2P_Cfg9_SW_Ver_Byte15_39 "CSC软件版本号Byte15对应的ASCII码";
CM_ SG_ 2417618535 S2P_Cfg9_SW_Ver_Byte16_39 "CSC软件版本号最高字节Byte16对应的ASCII码";
CM_ SG_ 2417618536 S2P_Cfg9_SW_Ver_Byte9_40 "CSC软件版本号Byte9对应的ASCII码";
CM_ SG_ 2417618536 S2P_Cfg9_SW_Ver_Byte10_40 "CSC软件版本号Byte10对应的ASCII码";
CM_ SG_ 2417618536 S2P_Cfg9_SW_Ver_Byte11_40 "CSC软件版本号Byte11对应的ASCII码";
CM_ SG_ 2417618536 S2P_Cfg9_SW_Ver_Byte12_40 "CSC软件版本号Byte12对应的ASCII码";
CM_ SG_ 2417618536 S2P_Cfg9_SW_Ver_Byte13_40 "CSC软件版本号Byte13对应的ASCII码";
CM_ SG_ 2417618536 S2P_Cfg9_SW_Ver_Byte14_40 "CSC软件版本号Byte14对应的ASCII码";
CM_ SG_ 2417618536 S2P_Cfg9_SW_Ver_Byte15_40 "CSC软件版本号Byte15对应的ASCII码";
CM_ SG_ 2417618536 S2P_Cfg9_SW_Ver_Byte16_40 "CSC软件版本号最高字节Byte16对应的ASCII码";
CM_ SG_ 2417618537 S2P_Cfg9_SW_Ver_Byte9_41 "CSC软件版本号Byte9对应的ASCII码";
CM_ SG_ 2417618537 S2P_Cfg9_SW_Ver_Byte10_41 "CSC软件版本号Byte10对应的ASCII码";
CM_ SG_ 2417618537 S2P_Cfg9_SW_Ver_Byte11_41 "CSC软件版本号Byte11对应的ASCII码";
CM_ SG_ 2417618537 S2P_Cfg9_SW_Ver_Byte12_41 "CSC软件版本号Byte12对应的ASCII码";
CM_ SG_ 2417618537 S2P_Cfg9_SW_Ver_Byte13_41 "CSC软件版本号Byte13对应的ASCII码";
CM_ SG_ 2417618537 S2P_Cfg9_SW_Ver_Byte14_41 "CSC软件版本号Byte14对应的ASCII码";
CM_ SG_ 2417618537 S2P_Cfg9_SW_Ver_Byte15_41 "CSC软件版本号Byte15对应的ASCII码";
CM_ SG_ 2417618537 S2P_Cfg9_SW_Ver_Byte16_41 "CSC软件版本号最高字节Byte16对应的ASCII码";
CM_ SG_ 2417618538 S2P_Cfg9_SW_Ver_Byte9_42 "CSC软件版本号Byte9对应的ASCII码";
CM_ SG_ 2417618538 S2P_Cfg9_SW_Ver_Byte10_42 "CSC软件版本号Byte10对应的ASCII码";
CM_ SG_ 2417618538 S2P_Cfg9_SW_Ver_Byte11_42 "CSC软件版本号Byte11对应的ASCII码";
CM_ SG_ 2417618538 S2P_Cfg9_SW_Ver_Byte12_42 "CSC软件版本号Byte12对应的ASCII码";
CM_ SG_ 2417618538 S2P_Cfg9_SW_Ver_Byte13_42 "CSC软件版本号Byte13对应的ASCII码";
CM_ SG_ 2417618538 S2P_Cfg9_SW_Ver_Byte14_42 "CSC软件版本号Byte14对应的ASCII码";
CM_ SG_ 2417618538 S2P_Cfg9_SW_Ver_Byte15_42 "CSC软件版本号Byte15对应的ASCII码";
CM_ SG_ 2417618538 S2P_Cfg9_SW_Ver_Byte16_42 "CSC软件版本号最高字节Byte16对应的ASCII码";
CM_ SG_ 2417618539 S2P_Cfg9_SW_Ver_Byte9_43 "CSC软件版本号Byte9对应的ASCII码";
CM_ SG_ 2417618539 S2P_Cfg9_SW_Ver_Byte10_43 "CSC软件版本号Byte10对应的ASCII码";
CM_ SG_ 2417618539 S2P_Cfg9_SW_Ver_Byte11_43 "CSC软件版本号Byte11对应的ASCII码";
CM_ SG_ 2417618539 S2P_Cfg9_SW_Ver_Byte12_43 "CSC软件版本号Byte12对应的ASCII码";
CM_ SG_ 2417618539 S2P_Cfg9_SW_Ver_Byte13_43 "CSC软件版本号Byte13对应的ASCII码";
CM_ SG_ 2417618539 S2P_Cfg9_SW_Ver_Byte14_43 "CSC软件版本号Byte14对应的ASCII码";
CM_ SG_ 2417618539 S2P_Cfg9_SW_Ver_Byte15_43 "CSC软件版本号Byte15对应的ASCII码";
CM_ SG_ 2417618539 S2P_Cfg9_SW_Ver_Byte16_43 "CSC软件版本号最高字节Byte16对应的ASCII码";
CM_ SG_ 2417618540 S2P_Cfg9_SW_Ver_Byte9_44 "CSC软件版本号Byte9对应的ASCII码";
CM_ SG_ 2417618540 S2P_Cfg9_SW_Ver_Byte10_44 "CSC软件版本号Byte10对应的ASCII码";
CM_ SG_ 2417618540 S2P_Cfg9_SW_Ver_Byte11_44 "CSC软件版本号Byte11对应的ASCII码";
CM_ SG_ 2417618540 S2P_Cfg9_SW_Ver_Byte12_44 "CSC软件版本号Byte12对应的ASCII码";
CM_ SG_ 2417618540 S2P_Cfg9_SW_Ver_Byte13_44 "CSC软件版本号Byte13对应的ASCII码";
CM_ SG_ 2417618540 S2P_Cfg9_SW_Ver_Byte14_44 "CSC软件版本号Byte14对应的ASCII码";
CM_ SG_ 2417618540 S2P_Cfg9_SW_Ver_Byte15_44 "CSC软件版本号Byte15对应的ASCII码";
CM_ SG_ 2417618540 S2P_Cfg9_SW_Ver_Byte16_44 "CSC软件版本号最高字节Byte16对应的ASCII码";
CM_ SG_ 2417618541 S2P_Cfg9_SW_Ver_Byte9_45 "CSC软件版本号Byte9对应的ASCII码";
CM_ SG_ 2417618541 S2P_Cfg9_SW_Ver_Byte10_45 "CSC软件版本号Byte10对应的ASCII码";
CM_ SG_ 2417618541 S2P_Cfg9_SW_Ver_Byte11_45 "CSC软件版本号Byte11对应的ASCII码";
CM_ SG_ 2417618541 S2P_Cfg9_SW_Ver_Byte12_45 "CSC软件版本号Byte12对应的ASCII码";
CM_ SG_ 2417618541 S2P_Cfg9_SW_Ver_Byte13_45 "CSC软件版本号Byte13对应的ASCII码";
CM_ SG_ 2417618541 S2P_Cfg9_SW_Ver_Byte14_45 "CSC软件版本号Byte14对应的ASCII码";
CM_ SG_ 2417618541 S2P_Cfg9_SW_Ver_Byte15_45 "CSC软件版本号Byte15对应的ASCII码";
CM_ SG_ 2417618541 S2P_Cfg9_SW_Ver_Byte16_45 "CSC软件版本号最高字节Byte16对应的ASCII码";
CM_ SG_ 2417618542 S2P_Cfg9_SW_Ver_Byte9_46 "CSC软件版本号Byte9对应的ASCII码";
CM_ SG_ 2417618542 S2P_Cfg9_SW_Ver_Byte10_46 "CSC软件版本号Byte10对应的ASCII码";
CM_ SG_ 2417618542 S2P_Cfg9_SW_Ver_Byte11_46 "CSC软件版本号Byte11对应的ASCII码";
CM_ SG_ 2417618542 S2P_Cfg9_SW_Ver_Byte12_46 "CSC软件版本号Byte12对应的ASCII码";
CM_ SG_ 2417618542 S2P_Cfg9_SW_Ver_Byte13_46 "CSC软件版本号Byte13对应的ASCII码";
CM_ SG_ 2417618542 S2P_Cfg9_SW_Ver_Byte14_46 "CSC软件版本号Byte14对应的ASCII码";
CM_ SG_ 2417618542 S2P_Cfg9_SW_Ver_Byte15_46 "CSC软件版本号Byte15对应的ASCII码";
CM_ SG_ 2417618542 S2P_Cfg9_SW_Ver_Byte16_46 "CSC软件版本号最高字节Byte16对应的ASCII码";
CM_ SG_ 2417618543 S2P_Cfg9_SW_Ver_Byte9_47 "CSC软件版本号Byte9对应的ASCII码";
CM_ SG_ 2417618543 S2P_Cfg9_SW_Ver_Byte10_47 "CSC软件版本号Byte10对应的ASCII码";
CM_ SG_ 2417618543 S2P_Cfg9_SW_Ver_Byte11_47 "CSC软件版本号Byte11对应的ASCII码";
CM_ SG_ 2417618543 S2P_Cfg9_SW_Ver_Byte12_47 "CSC软件版本号Byte12对应的ASCII码";
CM_ SG_ 2417618543 S2P_Cfg9_SW_Ver_Byte13_47 "CSC软件版本号Byte13对应的ASCII码";
CM_ SG_ 2417618543 S2P_Cfg9_SW_Ver_Byte14_47 "CSC软件版本号Byte14对应的ASCII码";
CM_ SG_ 2417618543 S2P_Cfg9_SW_Ver_Byte15_47 "CSC软件版本号Byte15对应的ASCII码";
CM_ SG_ 2417618543 S2P_Cfg9_SW_Ver_Byte16_47 "CSC软件版本号最高字节Byte16对应的ASCII码";
CM_ SG_ 2417618544 S2P_Cfg9_SW_Ver_Byte9_48 "CSC软件版本号Byte9对应的ASCII码";
CM_ SG_ 2417618544 S2P_Cfg9_SW_Ver_Byte10_48 "CSC软件版本号Byte10对应的ASCII码";
CM_ SG_ 2417618544 S2P_Cfg9_SW_Ver_Byte11_48 "CSC软件版本号Byte11对应的ASCII码";
CM_ SG_ 2417618544 S2P_Cfg9_SW_Ver_Byte12_48 "CSC软件版本号Byte12对应的ASCII码";
CM_ SG_ 2417618544 S2P_Cfg9_SW_Ver_Byte13_48 "CSC软件版本号Byte13对应的ASCII码";
CM_ SG_ 2417618544 S2P_Cfg9_SW_Ver_Byte14_48 "CSC软件版本号Byte14对应的ASCII码";
CM_ SG_ 2417618544 S2P_Cfg9_SW_Ver_Byte15_48 "CSC软件版本号Byte15对应的ASCII码";
CM_ SG_ 2417618544 S2P_Cfg9_SW_Ver_Byte16_48 "CSC软件版本号最高字节Byte16对应的ASCII码";
CM_ SG_ 2417618545 S2P_Cfg9_SW_Ver_Byte9_49 "CSC软件版本号Byte9对应的ASCII码";
CM_ SG_ 2417618545 S2P_Cfg9_SW_Ver_Byte10_49 "CSC软件版本号Byte10对应的ASCII码";
CM_ SG_ 2417618545 S2P_Cfg9_SW_Ver_Byte11_49 "CSC软件版本号Byte11对应的ASCII码";
CM_ SG_ 2417618545 S2P_Cfg9_SW_Ver_Byte12_49 "CSC软件版本号Byte12对应的ASCII码";
CM_ SG_ 2417618545 S2P_Cfg9_SW_Ver_Byte13_49 "CSC软件版本号Byte13对应的ASCII码";
CM_ SG_ 2417618545 S2P_Cfg9_SW_Ver_Byte14_49 "CSC软件版本号Byte14对应的ASCII码";
CM_ SG_ 2417618545 S2P_Cfg9_SW_Ver_Byte15_49 "CSC软件版本号Byte15对应的ASCII码";
CM_ SG_ 2417618545 S2P_Cfg9_SW_Ver_Byte16_49 "CSC软件版本号最高字节Byte16对应的ASCII码";
CM_ SG_ 2417618546 S2P_Cfg9_SW_Ver_Byte9_50 "CSC软件版本号Byte9对应的ASCII码";
CM_ SG_ 2417618546 S2P_Cfg9_SW_Ver_Byte10_50 "CSC软件版本号Byte10对应的ASCII码";
CM_ SG_ 2417618546 S2P_Cfg9_SW_Ver_Byte11_50 "CSC软件版本号Byte11对应的ASCII码";
CM_ SG_ 2417618546 S2P_Cfg9_SW_Ver_Byte12_50 "CSC软件版本号Byte12对应的ASCII码";
CM_ SG_ 2417618546 S2P_Cfg9_SW_Ver_Byte13_50 "CSC软件版本号Byte13对应的ASCII码";
CM_ SG_ 2417618546 S2P_Cfg9_SW_Ver_Byte14_50 "CSC软件版本号Byte14对应的ASCII码";
CM_ SG_ 2417618546 S2P_Cfg9_SW_Ver_Byte15_50 "CSC软件版本号Byte15对应的ASCII码";
CM_ SG_ 2417618546 S2P_Cfg9_SW_Ver_Byte16_50 "CSC软件版本号最高字节Byte16对应的ASCII码";
CM_ SG_ 2417618547 S2P_Cfg9_SW_Ver_Byte9_51 "CSC软件版本号Byte9对应的ASCII码";
CM_ SG_ 2417618547 S2P_Cfg9_SW_Ver_Byte10_51 "CSC软件版本号Byte10对应的ASCII码";
CM_ SG_ 2417618547 S2P_Cfg9_SW_Ver_Byte11_51 "CSC软件版本号Byte11对应的ASCII码";
CM_ SG_ 2417618547 S2P_Cfg9_SW_Ver_Byte12_51 "CSC软件版本号Byte12对应的ASCII码";
CM_ SG_ 2417618547 S2P_Cfg9_SW_Ver_Byte13_51 "CSC软件版本号Byte13对应的ASCII码";
CM_ SG_ 2417618547 S2P_Cfg9_SW_Ver_Byte14_51 "CSC软件版本号Byte14对应的ASCII码";
CM_ SG_ 2417618547 S2P_Cfg9_SW_Ver_Byte15_51 "CSC软件版本号Byte15对应的ASCII码";
CM_ SG_ 2417618547 S2P_Cfg9_SW_Ver_Byte16_51 "CSC软件版本号最高字节Byte16对应的ASCII码";
CM_ SG_ 2417618548 S2P_Cfg9_SW_Ver_Byte9_52 "CSC软件版本号Byte9对应的ASCII码";
CM_ SG_ 2417618548 S2P_Cfg9_SW_Ver_Byte10_52 "CSC软件版本号Byte10对应的ASCII码";
CM_ SG_ 2417618548 S2P_Cfg9_SW_Ver_Byte11_52 "CSC软件版本号Byte11对应的ASCII码";
CM_ SG_ 2417618548 S2P_Cfg9_SW_Ver_Byte12_52 "CSC软件版本号Byte12对应的ASCII码";
CM_ SG_ 2417618548 S2P_Cfg9_SW_Ver_Byte13_52 "CSC软件版本号Byte13对应的ASCII码";
CM_ SG_ 2417618548 S2P_Cfg9_SW_Ver_Byte14_52 "CSC软件版本号Byte14对应的ASCII码";
CM_ SG_ 2417618548 S2P_Cfg9_SW_Ver_Byte15_52 "CSC软件版本号Byte15对应的ASCII码";
CM_ SG_ 2417618548 S2P_Cfg9_SW_Ver_Byte16_52 "CSC软件版本号最高字节Byte16对应的ASCII码";
CM_ SG_ 2417618549 S2P_Cfg9_SW_Ver_Byte9_53 "CSC软件版本号Byte9对应的ASCII码";
CM_ SG_ 2417618549 S2P_Cfg9_SW_Ver_Byte10_53 "CSC软件版本号Byte10对应的ASCII码";
CM_ SG_ 2417618549 S2P_Cfg9_SW_Ver_Byte11_53 "CSC软件版本号Byte11对应的ASCII码";
CM_ SG_ 2417618549 S2P_Cfg9_SW_Ver_Byte12_53 "CSC软件版本号Byte12对应的ASCII码";
CM_ SG_ 2417618549 S2P_Cfg9_SW_Ver_Byte13_53 "CSC软件版本号Byte13对应的ASCII码";
CM_ SG_ 2417618549 S2P_Cfg9_SW_Ver_Byte14_53 "CSC软件版本号Byte14对应的ASCII码";
CM_ SG_ 2417618549 S2P_Cfg9_SW_Ver_Byte15_53 "CSC软件版本号Byte15对应的ASCII码";
CM_ SG_ 2417618549 S2P_Cfg9_SW_Ver_Byte16_53 "CSC软件版本号最高字节Byte16对应的ASCII码";
CM_ SG_ 2417618550 S2P_Cfg9_SW_Ver_Byte9_54 "CSC软件版本号Byte9对应的ASCII码";
CM_ SG_ 2417618550 S2P_Cfg9_SW_Ver_Byte10_54 "CSC软件版本号Byte10对应的ASCII码";
CM_ SG_ 2417618550 S2P_Cfg9_SW_Ver_Byte11_54 "CSC软件版本号Byte11对应的ASCII码";
CM_ SG_ 2417618550 S2P_Cfg9_SW_Ver_Byte12_54 "CSC软件版本号Byte12对应的ASCII码";
CM_ SG_ 2417618550 S2P_Cfg9_SW_Ver_Byte13_54 "CSC软件版本号Byte13对应的ASCII码";
CM_ SG_ 2417618550 S2P_Cfg9_SW_Ver_Byte14_54 "CSC软件版本号Byte14对应的ASCII码";
CM_ SG_ 2417618550 S2P_Cfg9_SW_Ver_Byte15_54 "CSC软件版本号Byte15对应的ASCII码";
CM_ SG_ 2417618550 S2P_Cfg9_SW_Ver_Byte16_54 "CSC软件版本号最高字节Byte16对应的ASCII码";
CM_ SG_ 2417618551 S2P_Cfg9_SW_Ver_Byte9_55 "CSC软件版本号Byte9对应的ASCII码";
CM_ SG_ 2417618551 S2P_Cfg9_SW_Ver_Byte10_55 "CSC软件版本号Byte10对应的ASCII码";
CM_ SG_ 2417618551 S2P_Cfg9_SW_Ver_Byte11_55 "CSC软件版本号Byte11对应的ASCII码";
CM_ SG_ 2417618551 S2P_Cfg9_SW_Ver_Byte12_55 "CSC软件版本号Byte12对应的ASCII码";
CM_ SG_ 2417618551 S2P_Cfg9_SW_Ver_Byte13_55 "CSC软件版本号Byte13对应的ASCII码";
CM_ SG_ 2417618551 S2P_Cfg9_SW_Ver_Byte14_55 "CSC软件版本号Byte14对应的ASCII码";
CM_ SG_ 2417618551 S2P_Cfg9_SW_Ver_Byte15_55 "CSC软件版本号Byte15对应的ASCII码";
CM_ SG_ 2417618551 S2P_Cfg9_SW_Ver_Byte16_55 "CSC软件版本号最高字节Byte16对应的ASCII码";
CM_ SG_ 2417618552 S2P_Cfg9_SW_Ver_Byte9_56 "CSC软件版本号Byte9对应的ASCII码";
CM_ SG_ 2417618552 S2P_Cfg9_SW_Ver_Byte10_56 "CSC软件版本号Byte10对应的ASCII码";
CM_ SG_ 2417618552 S2P_Cfg9_SW_Ver_Byte11_56 "CSC软件版本号Byte11对应的ASCII码";
CM_ SG_ 2417618552 S2P_Cfg9_SW_Ver_Byte12_56 "CSC软件版本号Byte12对应的ASCII码";
CM_ SG_ 2417618552 S2P_Cfg9_SW_Ver_Byte13_56 "CSC软件版本号Byte13对应的ASCII码";
CM_ SG_ 2417618552 S2P_Cfg9_SW_Ver_Byte14_56 "CSC软件版本号Byte14对应的ASCII码";
CM_ SG_ 2417618552 S2P_Cfg9_SW_Ver_Byte15_56 "CSC软件版本号Byte15对应的ASCII码";
CM_ SG_ 2417618552 S2P_Cfg9_SW_Ver_Byte16_56 "CSC软件版本号最高字节Byte16对应的ASCII码";
CM_ SG_ 2417618553 S2P_Cfg9_SW_Ver_Byte9_57 "CSC软件版本号Byte9对应的ASCII码";
CM_ SG_ 2417618553 S2P_Cfg9_SW_Ver_Byte10_57 "CSC软件版本号Byte10对应的ASCII码";
CM_ SG_ 2417618553 S2P_Cfg9_SW_Ver_Byte11_57 "CSC软件版本号Byte11对应的ASCII码";
CM_ SG_ 2417618553 S2P_Cfg9_SW_Ver_Byte12_57 "CSC软件版本号Byte12对应的ASCII码";
CM_ SG_ 2417618553 S2P_Cfg9_SW_Ver_Byte13_57 "CSC软件版本号Byte13对应的ASCII码";
CM_ SG_ 2417618553 S2P_Cfg9_SW_Ver_Byte14_57 "CSC软件版本号Byte14对应的ASCII码";
CM_ SG_ 2417618553 S2P_Cfg9_SW_Ver_Byte15_57 "CSC软件版本号Byte15对应的ASCII码";
CM_ SG_ 2417618553 S2P_Cfg9_SW_Ver_Byte16_57 "CSC软件版本号最高字节Byte16对应的ASCII码";
CM_ SG_ 2417618554 S2P_Cfg9_SW_Ver_Byte9_58 "CSC软件版本号Byte9对应的ASCII码";
CM_ SG_ 2417618554 S2P_Cfg9_SW_Ver_Byte10_58 "CSC软件版本号Byte10对应的ASCII码";
CM_ SG_ 2417618554 S2P_Cfg9_SW_Ver_Byte11_58 "CSC软件版本号Byte11对应的ASCII码";
CM_ SG_ 2417618554 S2P_Cfg9_SW_Ver_Byte12_58 "CSC软件版本号Byte12对应的ASCII码";
CM_ SG_ 2417618554 S2P_Cfg9_SW_Ver_Byte13_58 "CSC软件版本号Byte13对应的ASCII码";
CM_ SG_ 2417618554 S2P_Cfg9_SW_Ver_Byte14_58 "CSC软件版本号Byte14对应的ASCII码";
CM_ SG_ 2417618554 S2P_Cfg9_SW_Ver_Byte15_58 "CSC软件版本号Byte15对应的ASCII码";
CM_ SG_ 2417618554 S2P_Cfg9_SW_Ver_Byte16_58 "CSC软件版本号最高字节Byte16对应的ASCII码";
CM_ SG_ 2417618555 S2P_Cfg9_SW_Ver_Byte9_59 "CSC软件版本号Byte9对应的ASCII码";
CM_ SG_ 2417618555 S2P_Cfg9_SW_Ver_Byte10_59 "CSC软件版本号Byte10对应的ASCII码";
CM_ SG_ 2417618555 S2P_Cfg9_SW_Ver_Byte11_59 "CSC软件版本号Byte11对应的ASCII码";
CM_ SG_ 2417618555 S2P_Cfg9_SW_Ver_Byte12_59 "CSC软件版本号Byte12对应的ASCII码";
CM_ SG_ 2417618555 S2P_Cfg9_SW_Ver_Byte13_59 "CSC软件版本号Byte13对应的ASCII码";
CM_ SG_ 2417618555 S2P_Cfg9_SW_Ver_Byte14_59 "CSC软件版本号Byte14对应的ASCII码";
CM_ SG_ 2417618555 S2P_Cfg9_SW_Ver_Byte15_59 "CSC软件版本号Byte15对应的ASCII码";
CM_ SG_ 2417618555 S2P_Cfg9_SW_Ver_Byte16_59 "CSC软件版本号最高字节Byte16对应的ASCII码";
CM_ SG_ 2417618556 S2P_Cfg9_SW_Ver_Byte9_60 "CSC软件版本号Byte9对应的ASCII码";
CM_ SG_ 2417618556 S2P_Cfg9_SW_Ver_Byte10_60 "CSC软件版本号Byte10对应的ASCII码";
CM_ SG_ 2417618556 S2P_Cfg9_SW_Ver_Byte11_60 "CSC软件版本号Byte11对应的ASCII码";
CM_ SG_ 2417618556 S2P_Cfg9_SW_Ver_Byte12_60 "CSC软件版本号Byte12对应的ASCII码";
CM_ SG_ 2417618556 S2P_Cfg9_SW_Ver_Byte13_60 "CSC软件版本号Byte13对应的ASCII码";
CM_ SG_ 2417618556 S2P_Cfg9_SW_Ver_Byte14_60 "CSC软件版本号Byte14对应的ASCII码";
CM_ SG_ 2417618556 S2P_Cfg9_SW_Ver_Byte15_60 "CSC软件版本号Byte15对应的ASCII码";
CM_ SG_ 2417618556 S2P_Cfg9_SW_Ver_Byte16_60 "CSC软件版本号最高字节Byte16对应的ASCII码";
CM_ SG_ 2417618557 S2P_Cfg9_SW_Ver_Byte9_61 "CSC软件版本号Byte9对应的ASCII码";
CM_ SG_ 2417618557 S2P_Cfg9_SW_Ver_Byte10_61 "CSC软件版本号Byte10对应的ASCII码";
CM_ SG_ 2417618557 S2P_Cfg9_SW_Ver_Byte11_61 "CSC软件版本号Byte11对应的ASCII码";
CM_ SG_ 2417618557 S2P_Cfg9_SW_Ver_Byte12_61 "CSC软件版本号Byte12对应的ASCII码";
CM_ SG_ 2417618557 S2P_Cfg9_SW_Ver_Byte13_61 "CSC软件版本号Byte13对应的ASCII码";
CM_ SG_ 2417618557 S2P_Cfg9_SW_Ver_Byte14_61 "CSC软件版本号Byte14对应的ASCII码";
CM_ SG_ 2417618557 S2P_Cfg9_SW_Ver_Byte15_61 "CSC软件版本号Byte15对应的ASCII码";
CM_ SG_ 2417618557 S2P_Cfg9_SW_Ver_Byte16_61 "CSC软件版本号最高字节Byte16对应的ASCII码";
CM_ SG_ 2417618558 S2P_Cfg9_SW_Ver_Byte9_62 "CSC软件版本号Byte9对应的ASCII码";
CM_ SG_ 2417618558 S2P_Cfg9_SW_Ver_Byte10_62 "CSC软件版本号Byte10对应的ASCII码";
CM_ SG_ 2417618558 S2P_Cfg9_SW_Ver_Byte11_62 "CSC软件版本号Byte11对应的ASCII码";
CM_ SG_ 2417618558 S2P_Cfg9_SW_Ver_Byte12_62 "CSC软件版本号Byte12对应的ASCII码";
CM_ SG_ 2417618558 S2P_Cfg9_SW_Ver_Byte13_62 "CSC软件版本号Byte13对应的ASCII码";
CM_ SG_ 2417618558 S2P_Cfg9_SW_Ver_Byte14_62 "CSC软件版本号Byte14对应的ASCII码";
CM_ SG_ 2417618558 S2P_Cfg9_SW_Ver_Byte15_62 "CSC软件版本号Byte15对应的ASCII码";
CM_ SG_ 2417618558 S2P_Cfg9_SW_Ver_Byte16_62 "CSC软件版本号最高字节Byte16对应的ASCII码";
CM_ SG_ 2417618559 S2P_Cfg9_SW_Ver_Byte9_63 "CSC软件版本号Byte9对应的ASCII码";
CM_ SG_ 2417618559 S2P_Cfg9_SW_Ver_Byte10_63 "CSC软件版本号Byte10对应的ASCII码";
CM_ SG_ 2417618559 S2P_Cfg9_SW_Ver_Byte11_63 "CSC软件版本号Byte11对应的ASCII码";
CM_ SG_ 2417618559 S2P_Cfg9_SW_Ver_Byte12_63 "CSC软件版本号Byte12对应的ASCII码";
CM_ SG_ 2417618559 S2P_Cfg9_SW_Ver_Byte13_63 "CSC软件版本号Byte13对应的ASCII码";
CM_ SG_ 2417618559 S2P_Cfg9_SW_Ver_Byte14_63 "CSC软件版本号Byte14对应的ASCII码";
CM_ SG_ 2417618559 S2P_Cfg9_SW_Ver_Byte15_63 "CSC软件版本号Byte15对应的ASCII码";
CM_ SG_ 2417618559 S2P_Cfg9_SW_Ver_Byte16_63 "CSC软件版本号最高字节Byte16对应的ASCII码";
CM_ SG_ 2417684033 S2P_Cfg10_HW_Ver_Byte1_01 "CSC硬件版本号最低字节Byte1对应的ASCII码";
CM_ SG_ 2417684033 S2P_Cfg10_HW_Ver_Byte2_01 "CSC硬件版本号Byte2对应的ASCII码";
CM_ SG_ 2417684033 S2P_Cfg10_HW_Ver_Byte3_01 "CSC硬件版本号Byte3对应的ASCII码";
CM_ SG_ 2417684033 S2P_Cfg10_HW_Ver_Byte4_01 "CSC硬件版本号Byte4对应的ASCII码";
CM_ SG_ 2417684033 S2P_Cfg10_HW_Ver_Byte5_01 "CSC硬件版本号Byte5对应的ASCII码";
CM_ SG_ 2417684033 S2P_Cfg10_HW_Ver_Byte6_01 "CSC硬件版本号Byte6对应的ASCII码";
CM_ SG_ 2417684033 S2P_Cfg10_HW_Ver_Byte7_01 "CSC硬件版本号Byte7对应的ASCII码";
CM_ SG_ 2417684033 S2P_Cfg10_HW_Ver_Byte8_01 "CSC硬件版本号Byte8对应的ASCII码";
CM_ SG_ 2417684034 S2P_Cfg10_HW_Ver_Byte1_02 "CSC硬件版本号最低字节Byte1对应的ASCII码";
CM_ SG_ 2417684034 S2P_Cfg10_HW_Ver_Byte2_02 "CSC硬件版本号Byte2对应的ASCII码";
CM_ SG_ 2417684034 S2P_Cfg10_HW_Ver_Byte3_02 "CSC硬件版本号Byte3对应的ASCII码";
CM_ SG_ 2417684034 S2P_Cfg10_HW_Ver_Byte4_02 "CSC硬件版本号Byte4对应的ASCII码";
CM_ SG_ 2417684034 S2P_Cfg10_HW_Ver_Byte5_02 "CSC硬件版本号Byte5对应的ASCII码";
CM_ SG_ 2417684034 S2P_Cfg10_HW_Ver_Byte6_02 "CSC硬件版本号Byte6对应的ASCII码";
CM_ SG_ 2417684034 S2P_Cfg10_HW_Ver_Byte7_02 "CSC硬件版本号Byte7对应的ASCII码";
CM_ SG_ 2417684034 S2P_Cfg10_HW_Ver_Byte8_02 "CSC硬件版本号Byte8对应的ASCII码";
CM_ SG_ 2417684035 S2P_Cfg10_HW_Ver_Byte1_03 "CSC硬件版本号最低字节Byte1对应的ASCII码";
CM_ SG_ 2417684035 S2P_Cfg10_HW_Ver_Byte2_03 "CSC硬件版本号Byte2对应的ASCII码";
CM_ SG_ 2417684035 S2P_Cfg10_HW_Ver_Byte3_03 "CSC硬件版本号Byte3对应的ASCII码";
CM_ SG_ 2417684035 S2P_Cfg10_HW_Ver_Byte4_03 "CSC硬件版本号Byte4对应的ASCII码";
CM_ SG_ 2417684035 S2P_Cfg10_HW_Ver_Byte5_03 "CSC硬件版本号Byte5对应的ASCII码";
CM_ SG_ 2417684035 S2P_Cfg10_HW_Ver_Byte6_03 "CSC硬件版本号Byte6对应的ASCII码";
CM_ SG_ 2417684035 S2P_Cfg10_HW_Ver_Byte7_03 "CSC硬件版本号Byte7对应的ASCII码";
CM_ SG_ 2417684035 S2P_Cfg10_HW_Ver_Byte8_03 "CSC硬件版本号Byte8对应的ASCII码";
CM_ SG_ 2417684036 S2P_Cfg10_HW_Ver_Byte1_04 "CSC硬件版本号最低字节Byte1对应的ASCII码";
CM_ SG_ 2417684036 S2P_Cfg10_HW_Ver_Byte2_04 "CSC硬件版本号Byte2对应的ASCII码";
CM_ SG_ 2417684036 S2P_Cfg10_HW_Ver_Byte3_04 "CSC硬件版本号Byte3对应的ASCII码";
CM_ SG_ 2417684036 S2P_Cfg10_HW_Ver_Byte4_04 "CSC硬件版本号Byte4对应的ASCII码";
CM_ SG_ 2417684036 S2P_Cfg10_HW_Ver_Byte5_04 "CSC硬件版本号Byte5对应的ASCII码";
CM_ SG_ 2417684036 S2P_Cfg10_HW_Ver_Byte6_04 "CSC硬件版本号Byte6对应的ASCII码";
CM_ SG_ 2417684036 S2P_Cfg10_HW_Ver_Byte7_04 "CSC硬件版本号Byte7对应的ASCII码";
CM_ SG_ 2417684036 S2P_Cfg10_HW_Ver_Byte8_04 "CSC硬件版本号Byte8对应的ASCII码";
CM_ SG_ 2417684037 S2P_Cfg10_HW_Ver_Byte1_05 "CSC硬件版本号最低字节Byte1对应的ASCII码";
CM_ SG_ 2417684037 S2P_Cfg10_HW_Ver_Byte2_05 "CSC硬件版本号Byte2对应的ASCII码";
CM_ SG_ 2417684037 S2P_Cfg10_HW_Ver_Byte3_05 "CSC硬件版本号Byte3对应的ASCII码";
CM_ SG_ 2417684037 S2P_Cfg10_HW_Ver_Byte4_05 "CSC硬件版本号Byte4对应的ASCII码";
CM_ SG_ 2417684037 S2P_Cfg10_HW_Ver_Byte5_05 "CSC硬件版本号Byte5对应的ASCII码";
CM_ SG_ 2417684037 S2P_Cfg10_HW_Ver_Byte6_05 "CSC硬件版本号Byte6对应的ASCII码";
CM_ SG_ 2417684037 S2P_Cfg10_HW_Ver_Byte7_05 "CSC硬件版本号Byte7对应的ASCII码";
CM_ SG_ 2417684037 S2P_Cfg10_HW_Ver_Byte8_05 "CSC硬件版本号Byte8对应的ASCII码";
CM_ SG_ 2417684038 S2P_Cfg10_HW_Ver_Byte1_06 "CSC硬件版本号最低字节Byte1对应的ASCII码";
CM_ SG_ 2417684038 S2P_Cfg10_HW_Ver_Byte2_06 "CSC硬件版本号Byte2对应的ASCII码";
CM_ SG_ 2417684038 S2P_Cfg10_HW_Ver_Byte3_06 "CSC硬件版本号Byte3对应的ASCII码";
CM_ SG_ 2417684038 S2P_Cfg10_HW_Ver_Byte4_06 "CSC硬件版本号Byte4对应的ASCII码";
CM_ SG_ 2417684038 S2P_Cfg10_HW_Ver_Byte5_06 "CSC硬件版本号Byte5对应的ASCII码";
CM_ SG_ 2417684038 S2P_Cfg10_HW_Ver_Byte6_06 "CSC硬件版本号Byte6对应的ASCII码";
CM_ SG_ 2417684038 S2P_Cfg10_HW_Ver_Byte7_06 "CSC硬件版本号Byte7对应的ASCII码";
CM_ SG_ 2417684038 S2P_Cfg10_HW_Ver_Byte8_06 "CSC硬件版本号Byte8对应的ASCII码";
CM_ SG_ 2417684039 S2P_Cfg10_HW_Ver_Byte1_07 "CSC硬件版本号最低字节Byte1对应的ASCII码";
CM_ SG_ 2417684039 S2P_Cfg10_HW_Ver_Byte2_07 "CSC硬件版本号Byte2对应的ASCII码";
CM_ SG_ 2417684039 S2P_Cfg10_HW_Ver_Byte3_07 "CSC硬件版本号Byte3对应的ASCII码";
CM_ SG_ 2417684039 S2P_Cfg10_HW_Ver_Byte4_07 "CSC硬件版本号Byte4对应的ASCII码";
CM_ SG_ 2417684039 S2P_Cfg10_HW_Ver_Byte5_07 "CSC硬件版本号Byte5对应的ASCII码";
CM_ SG_ 2417684039 S2P_Cfg10_HW_Ver_Byte6_07 "CSC硬件版本号Byte6对应的ASCII码";
CM_ SG_ 2417684039 S2P_Cfg10_HW_Ver_Byte7_07 "CSC硬件版本号Byte7对应的ASCII码";
CM_ SG_ 2417684039 S2P_Cfg10_HW_Ver_Byte8_07 "CSC硬件版本号Byte8对应的ASCII码";
CM_ SG_ 2417684040 S2P_Cfg10_HW_Ver_Byte1_08 "CSC硬件版本号最低字节Byte1对应的ASCII码";
CM_ SG_ 2417684040 S2P_Cfg10_HW_Ver_Byte2_08 "CSC硬件版本号Byte2对应的ASCII码";
CM_ SG_ 2417684040 S2P_Cfg10_HW_Ver_Byte3_08 "CSC硬件版本号Byte3对应的ASCII码";
CM_ SG_ 2417684040 S2P_Cfg10_HW_Ver_Byte4_08 "CSC硬件版本号Byte4对应的ASCII码";
CM_ SG_ 2417684040 S2P_Cfg10_HW_Ver_Byte5_08 "CSC硬件版本号Byte5对应的ASCII码";
CM_ SG_ 2417684040 S2P_Cfg10_HW_Ver_Byte6_08 "CSC硬件版本号Byte6对应的ASCII码";
CM_ SG_ 2417684040 S2P_Cfg10_HW_Ver_Byte7_08 "CSC硬件版本号Byte7对应的ASCII码";
CM_ SG_ 2417684040 S2P_Cfg10_HW_Ver_Byte8_08 "CSC硬件版本号Byte8对应的ASCII码";
CM_ SG_ 2417684041 S2P_Cfg10_HW_Ver_Byte1_09 "CSC硬件版本号最低字节Byte1对应的ASCII码";
CM_ SG_ 2417684041 S2P_Cfg10_HW_Ver_Byte2_09 "CSC硬件版本号Byte2对应的ASCII码";
CM_ SG_ 2417684041 S2P_Cfg10_HW_Ver_Byte3_09 "CSC硬件版本号Byte3对应的ASCII码";
CM_ SG_ 2417684041 S2P_Cfg10_HW_Ver_Byte4_09 "CSC硬件版本号Byte4对应的ASCII码";
CM_ SG_ 2417684041 S2P_Cfg10_HW_Ver_Byte5_09 "CSC硬件版本号Byte5对应的ASCII码";
CM_ SG_ 2417684041 S2P_Cfg10_HW_Ver_Byte6_09 "CSC硬件版本号Byte6对应的ASCII码";
CM_ SG_ 2417684041 S2P_Cfg10_HW_Ver_Byte7_09 "CSC硬件版本号Byte7对应的ASCII码";
CM_ SG_ 2417684041 S2P_Cfg10_HW_Ver_Byte8_09 "CSC硬件版本号Byte8对应的ASCII码";
CM_ SG_ 2417684042 S2P_Cfg10_HW_Ver_Byte1_10 "CSC硬件版本号最低字节Byte1对应的ASCII码";
CM_ SG_ 2417684042 S2P_Cfg10_HW_Ver_Byte2_10 "CSC硬件版本号Byte2对应的ASCII码";
CM_ SG_ 2417684042 S2P_Cfg10_HW_Ver_Byte3_10 "CSC硬件版本号Byte3对应的ASCII码";
CM_ SG_ 2417684042 S2P_Cfg10_HW_Ver_Byte4_10 "CSC硬件版本号Byte4对应的ASCII码";
CM_ SG_ 2417684042 S2P_Cfg10_HW_Ver_Byte5_10 "CSC硬件版本号Byte5对应的ASCII码";
CM_ SG_ 2417684042 S2P_Cfg10_HW_Ver_Byte6_10 "CSC硬件版本号Byte6对应的ASCII码";
CM_ SG_ 2417684042 S2P_Cfg10_HW_Ver_Byte7_10 "CSC硬件版本号Byte7对应的ASCII码";
CM_ SG_ 2417684042 S2P_Cfg10_HW_Ver_Byte8_10 "CSC硬件版本号Byte8对应的ASCII码";
CM_ SG_ 2417684043 S2P_Cfg10_HW_Ver_Byte1_11 "CSC硬件版本号最低字节Byte1对应的ASCII码";
CM_ SG_ 2417684043 S2P_Cfg10_HW_Ver_Byte2_11 "CSC硬件版本号Byte2对应的ASCII码";
CM_ SG_ 2417684043 S2P_Cfg10_HW_Ver_Byte3_11 "CSC硬件版本号Byte3对应的ASCII码";
CM_ SG_ 2417684043 S2P_Cfg10_HW_Ver_Byte4_11 "CSC硬件版本号Byte4对应的ASCII码";
CM_ SG_ 2417684043 S2P_Cfg10_HW_Ver_Byte5_11 "CSC硬件版本号Byte5对应的ASCII码";
CM_ SG_ 2417684043 S2P_Cfg10_HW_Ver_Byte6_11 "CSC硬件版本号Byte6对应的ASCII码";
CM_ SG_ 2417684043 S2P_Cfg10_HW_Ver_Byte7_11 "CSC硬件版本号Byte7对应的ASCII码";
CM_ SG_ 2417684043 S2P_Cfg10_HW_Ver_Byte8_11 "CSC硬件版本号Byte8对应的ASCII码";
CM_ SG_ 2417684044 S2P_Cfg10_HW_Ver_Byte1_12 "CSC硬件版本号最低字节Byte1对应的ASCII码";
CM_ SG_ 2417684044 S2P_Cfg10_HW_Ver_Byte2_12 "CSC硬件版本号Byte2对应的ASCII码";
CM_ SG_ 2417684044 S2P_Cfg10_HW_Ver_Byte3_12 "CSC硬件版本号Byte3对应的ASCII码";
CM_ SG_ 2417684044 S2P_Cfg10_HW_Ver_Byte4_12 "CSC硬件版本号Byte4对应的ASCII码";
CM_ SG_ 2417684044 S2P_Cfg10_HW_Ver_Byte5_12 "CSC硬件版本号Byte5对应的ASCII码";
CM_ SG_ 2417684044 S2P_Cfg10_HW_Ver_Byte6_12 "CSC硬件版本号Byte6对应的ASCII码";
CM_ SG_ 2417684044 S2P_Cfg10_HW_Ver_Byte7_12 "CSC硬件版本号Byte7对应的ASCII码";
CM_ SG_ 2417684044 S2P_Cfg10_HW_Ver_Byte8_12 "CSC硬件版本号Byte8对应的ASCII码";
CM_ SG_ 2417684045 S2P_Cfg10_HW_Ver_Byte1_13 "CSC硬件版本号最低字节Byte1对应的ASCII码";
CM_ SG_ 2417684045 S2P_Cfg10_HW_Ver_Byte2_13 "CSC硬件版本号Byte2对应的ASCII码";
CM_ SG_ 2417684045 S2P_Cfg10_HW_Ver_Byte3_13 "CSC硬件版本号Byte3对应的ASCII码";
CM_ SG_ 2417684045 S2P_Cfg10_HW_Ver_Byte4_13 "CSC硬件版本号Byte4对应的ASCII码";
CM_ SG_ 2417684045 S2P_Cfg10_HW_Ver_Byte5_13 "CSC硬件版本号Byte5对应的ASCII码";
CM_ SG_ 2417684045 S2P_Cfg10_HW_Ver_Byte6_13 "CSC硬件版本号Byte6对应的ASCII码";
CM_ SG_ 2417684045 S2P_Cfg10_HW_Ver_Byte7_13 "CSC硬件版本号Byte7对应的ASCII码";
CM_ SG_ 2417684045 S2P_Cfg10_HW_Ver_Byte8_13 "CSC硬件版本号Byte8对应的ASCII码";
CM_ SG_ 2417684046 S2P_Cfg10_HW_Ver_Byte1_14 "CSC硬件版本号最低字节Byte1对应的ASCII码";
CM_ SG_ 2417684046 S2P_Cfg10_HW_Ver_Byte2_14 "CSC硬件版本号Byte2对应的ASCII码";
CM_ SG_ 2417684046 S2P_Cfg10_HW_Ver_Byte3_14 "CSC硬件版本号Byte3对应的ASCII码";
CM_ SG_ 2417684046 S2P_Cfg10_HW_Ver_Byte4_14 "CSC硬件版本号Byte4对应的ASCII码";
CM_ SG_ 2417684046 S2P_Cfg10_HW_Ver_Byte5_14 "CSC硬件版本号Byte5对应的ASCII码";
CM_ SG_ 2417684046 S2P_Cfg10_HW_Ver_Byte6_14 "CSC硬件版本号Byte6对应的ASCII码";
CM_ SG_ 2417684046 S2P_Cfg10_HW_Ver_Byte7_14 "CSC硬件版本号Byte7对应的ASCII码";
CM_ SG_ 2417684046 S2P_Cfg10_HW_Ver_Byte8_14 "CSC硬件版本号Byte8对应的ASCII码";
CM_ SG_ 2417684047 S2P_Cfg10_HW_Ver_Byte1_15 "CSC硬件版本号最低字节Byte1对应的ASCII码";
CM_ SG_ 2417684047 S2P_Cfg10_HW_Ver_Byte2_15 "CSC硬件版本号Byte2对应的ASCII码";
CM_ SG_ 2417684047 S2P_Cfg10_HW_Ver_Byte3_15 "CSC硬件版本号Byte3对应的ASCII码";
CM_ SG_ 2417684047 S2P_Cfg10_HW_Ver_Byte4_15 "CSC硬件版本号Byte4对应的ASCII码";
CM_ SG_ 2417684047 S2P_Cfg10_HW_Ver_Byte5_15 "CSC硬件版本号Byte5对应的ASCII码";
CM_ SG_ 2417684047 S2P_Cfg10_HW_Ver_Byte6_15 "CSC硬件版本号Byte6对应的ASCII码";
CM_ SG_ 2417684047 S2P_Cfg10_HW_Ver_Byte7_15 "CSC硬件版本号Byte7对应的ASCII码";
CM_ SG_ 2417684047 S2P_Cfg10_HW_Ver_Byte8_15 "CSC硬件版本号Byte8对应的ASCII码";
CM_ SG_ 2417684048 S2P_Cfg10_HW_Ver_Byte1_16 "CSC硬件版本号最低字节Byte1对应的ASCII码";
CM_ SG_ 2417684048 S2P_Cfg10_HW_Ver_Byte2_16 "CSC硬件版本号Byte2对应的ASCII码";
CM_ SG_ 2417684048 S2P_Cfg10_HW_Ver_Byte3_16 "CSC硬件版本号Byte3对应的ASCII码";
CM_ SG_ 2417684048 S2P_Cfg10_HW_Ver_Byte4_16 "CSC硬件版本号Byte4对应的ASCII码";
CM_ SG_ 2417684048 S2P_Cfg10_HW_Ver_Byte5_16 "CSC硬件版本号Byte5对应的ASCII码";
CM_ SG_ 2417684048 S2P_Cfg10_HW_Ver_Byte6_16 "CSC硬件版本号Byte6对应的ASCII码";
CM_ SG_ 2417684048 S2P_Cfg10_HW_Ver_Byte7_16 "CSC硬件版本号Byte7对应的ASCII码";
CM_ SG_ 2417684048 S2P_Cfg10_HW_Ver_Byte8_16 "CSC硬件版本号Byte8对应的ASCII码";
CM_ SG_ 2417684049 S2P_Cfg10_HW_Ver_Byte1_17 "CSC硬件版本号最低字节Byte1对应的ASCII码";
CM_ SG_ 2417684049 S2P_Cfg10_HW_Ver_Byte2_17 "CSC硬件版本号Byte2对应的ASCII码";
CM_ SG_ 2417684049 S2P_Cfg10_HW_Ver_Byte3_17 "CSC硬件版本号Byte3对应的ASCII码";
CM_ SG_ 2417684049 S2P_Cfg10_HW_Ver_Byte4_17 "CSC硬件版本号Byte4对应的ASCII码";
CM_ SG_ 2417684049 S2P_Cfg10_HW_Ver_Byte5_17 "CSC硬件版本号Byte5对应的ASCII码";
CM_ SG_ 2417684049 S2P_Cfg10_HW_Ver_Byte6_17 "CSC硬件版本号Byte6对应的ASCII码";
CM_ SG_ 2417684049 S2P_Cfg10_HW_Ver_Byte7_17 "CSC硬件版本号Byte7对应的ASCII码";
CM_ SG_ 2417684049 S2P_Cfg10_HW_Ver_Byte8_17 "CSC硬件版本号Byte8对应的ASCII码";
CM_ SG_ 2417684050 S2P_Cfg10_HW_Ver_Byte1_18 "CSC硬件版本号最低字节Byte1对应的ASCII码";
CM_ SG_ 2417684050 S2P_Cfg10_HW_Ver_Byte2_18 "CSC硬件版本号Byte2对应的ASCII码";
CM_ SG_ 2417684050 S2P_Cfg10_HW_Ver_Byte3_18 "CSC硬件版本号Byte3对应的ASCII码";
CM_ SG_ 2417684050 S2P_Cfg10_HW_Ver_Byte4_18 "CSC硬件版本号Byte4对应的ASCII码";
CM_ SG_ 2417684050 S2P_Cfg10_HW_Ver_Byte5_18 "CSC硬件版本号Byte5对应的ASCII码";
CM_ SG_ 2417684050 S2P_Cfg10_HW_Ver_Byte6_18 "CSC硬件版本号Byte6对应的ASCII码";
CM_ SG_ 2417684050 S2P_Cfg10_HW_Ver_Byte7_18 "CSC硬件版本号Byte7对应的ASCII码";
CM_ SG_ 2417684050 S2P_Cfg10_HW_Ver_Byte8_18 "CSC硬件版本号Byte8对应的ASCII码";
CM_ SG_ 2417684051 S2P_Cfg10_HW_Ver_Byte1_19 "CSC硬件版本号最低字节Byte1对应的ASCII码";
CM_ SG_ 2417684051 S2P_Cfg10_HW_Ver_Byte2_19 "CSC硬件版本号Byte2对应的ASCII码";
CM_ SG_ 2417684051 S2P_Cfg10_HW_Ver_Byte3_19 "CSC硬件版本号Byte3对应的ASCII码";
CM_ SG_ 2417684051 S2P_Cfg10_HW_Ver_Byte4_19 "CSC硬件版本号Byte4对应的ASCII码";
CM_ SG_ 2417684051 S2P_Cfg10_HW_Ver_Byte5_19 "CSC硬件版本号Byte5对应的ASCII码";
CM_ SG_ 2417684051 S2P_Cfg10_HW_Ver_Byte6_19 "CSC硬件版本号Byte6对应的ASCII码";
CM_ SG_ 2417684051 S2P_Cfg10_HW_Ver_Byte7_19 "CSC硬件版本号Byte7对应的ASCII码";
CM_ SG_ 2417684051 S2P_Cfg10_HW_Ver_Byte8_19 "CSC硬件版本号Byte8对应的ASCII码";
CM_ SG_ 2417684052 S2P_Cfg10_HW_Ver_Byte1_20 "CSC硬件版本号最低字节Byte1对应的ASCII码";
CM_ SG_ 2417684052 S2P_Cfg10_HW_Ver_Byte2_20 "CSC硬件版本号Byte2对应的ASCII码";
CM_ SG_ 2417684052 S2P_Cfg10_HW_Ver_Byte3_20 "CSC硬件版本号Byte3对应的ASCII码";
CM_ SG_ 2417684052 S2P_Cfg10_HW_Ver_Byte4_20 "CSC硬件版本号Byte4对应的ASCII码";
CM_ SG_ 2417684052 S2P_Cfg10_HW_Ver_Byte5_20 "CSC硬件版本号Byte5对应的ASCII码";
CM_ SG_ 2417684052 S2P_Cfg10_HW_Ver_Byte6_20 "CSC硬件版本号Byte6对应的ASCII码";
CM_ SG_ 2417684052 S2P_Cfg10_HW_Ver_Byte7_20 "CSC硬件版本号Byte7对应的ASCII码";
CM_ SG_ 2417684052 S2P_Cfg10_HW_Ver_Byte8_20 "CSC硬件版本号Byte8对应的ASCII码";
CM_ SG_ 2417684053 S2P_Cfg10_HW_Ver_Byte1_21 "CSC硬件版本号最低字节Byte1对应的ASCII码";
CM_ SG_ 2417684053 S2P_Cfg10_HW_Ver_Byte2_21 "CSC硬件版本号Byte2对应的ASCII码";
CM_ SG_ 2417684053 S2P_Cfg10_HW_Ver_Byte3_21 "CSC硬件版本号Byte3对应的ASCII码";
CM_ SG_ 2417684053 S2P_Cfg10_HW_Ver_Byte4_21 "CSC硬件版本号Byte4对应的ASCII码";
CM_ SG_ 2417684053 S2P_Cfg10_HW_Ver_Byte5_21 "CSC硬件版本号Byte5对应的ASCII码";
CM_ SG_ 2417684053 S2P_Cfg10_HW_Ver_Byte6_21 "CSC硬件版本号Byte6对应的ASCII码";
CM_ SG_ 2417684053 S2P_Cfg10_HW_Ver_Byte7_21 "CSC硬件版本号Byte7对应的ASCII码";
CM_ SG_ 2417684053 S2P_Cfg10_HW_Ver_Byte8_21 "CSC硬件版本号Byte8对应的ASCII码";
CM_ SG_ 2417684054 S2P_Cfg10_HW_Ver_Byte1_22 "CSC硬件版本号最低字节Byte1对应的ASCII码";
CM_ SG_ 2417684054 S2P_Cfg10_HW_Ver_Byte2_22 "CSC硬件版本号Byte2对应的ASCII码";
CM_ SG_ 2417684054 S2P_Cfg10_HW_Ver_Byte3_22 "CSC硬件版本号Byte3对应的ASCII码";
CM_ SG_ 2417684054 S2P_Cfg10_HW_Ver_Byte4_22 "CSC硬件版本号Byte4对应的ASCII码";
CM_ SG_ 2417684054 S2P_Cfg10_HW_Ver_Byte5_22 "CSC硬件版本号Byte5对应的ASCII码";
CM_ SG_ 2417684054 S2P_Cfg10_HW_Ver_Byte6_22 "CSC硬件版本号Byte6对应的ASCII码";
CM_ SG_ 2417684054 S2P_Cfg10_HW_Ver_Byte7_22 "CSC硬件版本号Byte7对应的ASCII码";
CM_ SG_ 2417684054 S2P_Cfg10_HW_Ver_Byte8_22 "CSC硬件版本号Byte8对应的ASCII码";
CM_ SG_ 2417684055 S2P_Cfg10_HW_Ver_Byte1_23 "CSC硬件版本号最低字节Byte1对应的ASCII码";
CM_ SG_ 2417684055 S2P_Cfg10_HW_Ver_Byte2_23 "CSC硬件版本号Byte2对应的ASCII码";
CM_ SG_ 2417684055 S2P_Cfg10_HW_Ver_Byte3_23 "CSC硬件版本号Byte3对应的ASCII码";
CM_ SG_ 2417684055 S2P_Cfg10_HW_Ver_Byte4_23 "CSC硬件版本号Byte4对应的ASCII码";
CM_ SG_ 2417684055 S2P_Cfg10_HW_Ver_Byte5_23 "CSC硬件版本号Byte5对应的ASCII码";
CM_ SG_ 2417684055 S2P_Cfg10_HW_Ver_Byte6_23 "CSC硬件版本号Byte6对应的ASCII码";
CM_ SG_ 2417684055 S2P_Cfg10_HW_Ver_Byte7_23 "CSC硬件版本号Byte7对应的ASCII码";
CM_ SG_ 2417684055 S2P_Cfg10_HW_Ver_Byte8_23 "CSC硬件版本号Byte8对应的ASCII码";
CM_ SG_ 2417684056 S2P_Cfg10_HW_Ver_Byte1_24 "CSC硬件版本号最低字节Byte1对应的ASCII码";
CM_ SG_ 2417684056 S2P_Cfg10_HW_Ver_Byte2_24 "CSC硬件版本号Byte2对应的ASCII码";
CM_ SG_ 2417684056 S2P_Cfg10_HW_Ver_Byte3_24 "CSC硬件版本号Byte3对应的ASCII码";
CM_ SG_ 2417684056 S2P_Cfg10_HW_Ver_Byte4_24 "CSC硬件版本号Byte4对应的ASCII码";
CM_ SG_ 2417684056 S2P_Cfg10_HW_Ver_Byte5_24 "CSC硬件版本号Byte5对应的ASCII码";
CM_ SG_ 2417684056 S2P_Cfg10_HW_Ver_Byte6_24 "CSC硬件版本号Byte6对应的ASCII码";
CM_ SG_ 2417684056 S2P_Cfg10_HW_Ver_Byte7_24 "CSC硬件版本号Byte7对应的ASCII码";
CM_ SG_ 2417684056 S2P_Cfg10_HW_Ver_Byte8_24 "CSC硬件版本号Byte8对应的ASCII码";
CM_ SG_ 2417684057 S2P_Cfg10_HW_Ver_Byte1_25 "CSC硬件版本号最低字节Byte1对应的ASCII码";
CM_ SG_ 2417684057 S2P_Cfg10_HW_Ver_Byte2_25 "CSC硬件版本号Byte2对应的ASCII码";
CM_ SG_ 2417684057 S2P_Cfg10_HW_Ver_Byte3_25 "CSC硬件版本号Byte3对应的ASCII码";
CM_ SG_ 2417684057 S2P_Cfg10_HW_Ver_Byte4_25 "CSC硬件版本号Byte4对应的ASCII码";
CM_ SG_ 2417684057 S2P_Cfg10_HW_Ver_Byte5_25 "CSC硬件版本号Byte5对应的ASCII码";
CM_ SG_ 2417684057 S2P_Cfg10_HW_Ver_Byte6_25 "CSC硬件版本号Byte6对应的ASCII码";
CM_ SG_ 2417684057 S2P_Cfg10_HW_Ver_Byte7_25 "CSC硬件版本号Byte7对应的ASCII码";
CM_ SG_ 2417684057 S2P_Cfg10_HW_Ver_Byte8_25 "CSC硬件版本号Byte8对应的ASCII码";
CM_ SG_ 2417684058 S2P_Cfg10_HW_Ver_Byte1_26 "CSC硬件版本号最低字节Byte1对应的ASCII码";
CM_ SG_ 2417684058 S2P_Cfg10_HW_Ver_Byte2_26 "CSC硬件版本号Byte2对应的ASCII码";
CM_ SG_ 2417684058 S2P_Cfg10_HW_Ver_Byte3_26 "CSC硬件版本号Byte3对应的ASCII码";
CM_ SG_ 2417684058 S2P_Cfg10_HW_Ver_Byte4_26 "CSC硬件版本号Byte4对应的ASCII码";
CM_ SG_ 2417684058 S2P_Cfg10_HW_Ver_Byte5_26 "CSC硬件版本号Byte5对应的ASCII码";
CM_ SG_ 2417684058 S2P_Cfg10_HW_Ver_Byte6_26 "CSC硬件版本号Byte6对应的ASCII码";
CM_ SG_ 2417684058 S2P_Cfg10_HW_Ver_Byte7_26 "CSC硬件版本号Byte7对应的ASCII码";
CM_ SG_ 2417684058 S2P_Cfg10_HW_Ver_Byte8_26 "CSC硬件版本号Byte8对应的ASCII码";
CM_ SG_ 2417684059 S2P_Cfg10_HW_Ver_Byte1_27 "CSC硬件版本号最低字节Byte1对应的ASCII码";
CM_ SG_ 2417684059 S2P_Cfg10_HW_Ver_Byte2_27 "CSC硬件版本号Byte2对应的ASCII码";
CM_ SG_ 2417684059 S2P_Cfg10_HW_Ver_Byte3_27 "CSC硬件版本号Byte3对应的ASCII码";
CM_ SG_ 2417684059 S2P_Cfg10_HW_Ver_Byte4_27 "CSC硬件版本号Byte4对应的ASCII码";
CM_ SG_ 2417684059 S2P_Cfg10_HW_Ver_Byte5_27 "CSC硬件版本号Byte5对应的ASCII码";
CM_ SG_ 2417684059 S2P_Cfg10_HW_Ver_Byte6_27 "CSC硬件版本号Byte6对应的ASCII码";
CM_ SG_ 2417684059 S2P_Cfg10_HW_Ver_Byte7_27 "CSC硬件版本号Byte7对应的ASCII码";
CM_ SG_ 2417684059 S2P_Cfg10_HW_Ver_Byte8_27 "CSC硬件版本号Byte8对应的ASCII码";
CM_ SG_ 2417684060 S2P_Cfg10_HW_Ver_Byte1_28 "CSC硬件版本号最低字节Byte1对应的ASCII码";
CM_ SG_ 2417684060 S2P_Cfg10_HW_Ver_Byte2_28 "CSC硬件版本号Byte2对应的ASCII码";
CM_ SG_ 2417684060 S2P_Cfg10_HW_Ver_Byte3_28 "CSC硬件版本号Byte3对应的ASCII码";
CM_ SG_ 2417684060 S2P_Cfg10_HW_Ver_Byte4_28 "CSC硬件版本号Byte4对应的ASCII码";
CM_ SG_ 2417684060 S2P_Cfg10_HW_Ver_Byte5_28 "CSC硬件版本号Byte5对应的ASCII码";
CM_ SG_ 2417684060 S2P_Cfg10_HW_Ver_Byte6_28 "CSC硬件版本号Byte6对应的ASCII码";
CM_ SG_ 2417684060 S2P_Cfg10_HW_Ver_Byte7_28 "CSC硬件版本号Byte7对应的ASCII码";
CM_ SG_ 2417684060 S2P_Cfg10_HW_Ver_Byte8_28 "CSC硬件版本号Byte8对应的ASCII码";
CM_ SG_ 2417684061 S2P_Cfg10_HW_Ver_Byte1_29 "CSC硬件版本号最低字节Byte1对应的ASCII码";
CM_ SG_ 2417684061 S2P_Cfg10_HW_Ver_Byte2_29 "CSC硬件版本号Byte2对应的ASCII码";
CM_ SG_ 2417684061 S2P_Cfg10_HW_Ver_Byte3_29 "CSC硬件版本号Byte3对应的ASCII码";
CM_ SG_ 2417684061 S2P_Cfg10_HW_Ver_Byte4_29 "CSC硬件版本号Byte4对应的ASCII码";
CM_ SG_ 2417684061 S2P_Cfg10_HW_Ver_Byte5_29 "CSC硬件版本号Byte5对应的ASCII码";
CM_ SG_ 2417684061 S2P_Cfg10_HW_Ver_Byte6_29 "CSC硬件版本号Byte6对应的ASCII码";
CM_ SG_ 2417684061 S2P_Cfg10_HW_Ver_Byte7_29 "CSC硬件版本号Byte7对应的ASCII码";
CM_ SG_ 2417684061 S2P_Cfg10_HW_Ver_Byte8_29 "CSC硬件版本号Byte8对应的ASCII码";
CM_ SG_ 2417684062 S2P_Cfg10_HW_Ver_Byte1_30 "CSC硬件版本号最低字节Byte1对应的ASCII码";
CM_ SG_ 2417684062 S2P_Cfg10_HW_Ver_Byte2_30 "CSC硬件版本号Byte2对应的ASCII码";
CM_ SG_ 2417684062 S2P_Cfg10_HW_Ver_Byte3_30 "CSC硬件版本号Byte3对应的ASCII码";
CM_ SG_ 2417684062 S2P_Cfg10_HW_Ver_Byte4_30 "CSC硬件版本号Byte4对应的ASCII码";
CM_ SG_ 2417684062 S2P_Cfg10_HW_Ver_Byte5_30 "CSC硬件版本号Byte5对应的ASCII码";
CM_ SG_ 2417684062 S2P_Cfg10_HW_Ver_Byte6_30 "CSC硬件版本号Byte6对应的ASCII码";
CM_ SG_ 2417684062 S2P_Cfg10_HW_Ver_Byte7_30 "CSC硬件版本号Byte7对应的ASCII码";
CM_ SG_ 2417684062 S2P_Cfg10_HW_Ver_Byte8_30 "CSC硬件版本号Byte8对应的ASCII码";
CM_ SG_ 2417684063 S2P_Cfg10_HW_Ver_Byte1_31 "CSC硬件版本号最低字节Byte1对应的ASCII码";
CM_ SG_ 2417684063 S2P_Cfg10_HW_Ver_Byte2_31 "CSC硬件版本号Byte2对应的ASCII码";
CM_ SG_ 2417684063 S2P_Cfg10_HW_Ver_Byte3_31 "CSC硬件版本号Byte3对应的ASCII码";
CM_ SG_ 2417684063 S2P_Cfg10_HW_Ver_Byte4_31 "CSC硬件版本号Byte4对应的ASCII码";
CM_ SG_ 2417684063 S2P_Cfg10_HW_Ver_Byte5_31 "CSC硬件版本号Byte5对应的ASCII码";
CM_ SG_ 2417684063 S2P_Cfg10_HW_Ver_Byte6_31 "CSC硬件版本号Byte6对应的ASCII码";
CM_ SG_ 2417684063 S2P_Cfg10_HW_Ver_Byte7_31 "CSC硬件版本号Byte7对应的ASCII码";
CM_ SG_ 2417684063 S2P_Cfg10_HW_Ver_Byte8_31 "CSC硬件版本号Byte8对应的ASCII码";
CM_ SG_ 2417684064 S2P_Cfg10_HW_Ver_Byte1_32 "CSC硬件版本号最低字节Byte1对应的ASCII码";
CM_ SG_ 2417684064 S2P_Cfg10_HW_Ver_Byte2_32 "CSC硬件版本号Byte2对应的ASCII码";
CM_ SG_ 2417684064 S2P_Cfg10_HW_Ver_Byte3_32 "CSC硬件版本号Byte3对应的ASCII码";
CM_ SG_ 2417684064 S2P_Cfg10_HW_Ver_Byte4_32 "CSC硬件版本号Byte4对应的ASCII码";
CM_ SG_ 2417684064 S2P_Cfg10_HW_Ver_Byte5_32 "CSC硬件版本号Byte5对应的ASCII码";
CM_ SG_ 2417684064 S2P_Cfg10_HW_Ver_Byte6_32 "CSC硬件版本号Byte6对应的ASCII码";
CM_ SG_ 2417684064 S2P_Cfg10_HW_Ver_Byte7_32 "CSC硬件版本号Byte7对应的ASCII码";
CM_ SG_ 2417684064 S2P_Cfg10_HW_Ver_Byte8_32 "CSC硬件版本号Byte8对应的ASCII码";
CM_ SG_ 2417684065 S2P_Cfg10_HW_Ver_Byte1_33 "CSC硬件版本号最低字节Byte1对应的ASCII码";
CM_ SG_ 2417684065 S2P_Cfg10_HW_Ver_Byte2_33 "CSC硬件版本号Byte2对应的ASCII码";
CM_ SG_ 2417684065 S2P_Cfg10_HW_Ver_Byte3_33 "CSC硬件版本号Byte3对应的ASCII码";
CM_ SG_ 2417684065 S2P_Cfg10_HW_Ver_Byte4_33 "CSC硬件版本号Byte4对应的ASCII码";
CM_ SG_ 2417684065 S2P_Cfg10_HW_Ver_Byte5_33 "CSC硬件版本号Byte5对应的ASCII码";
CM_ SG_ 2417684065 S2P_Cfg10_HW_Ver_Byte6_33 "CSC硬件版本号Byte6对应的ASCII码";
CM_ SG_ 2417684065 S2P_Cfg10_HW_Ver_Byte7_33 "CSC硬件版本号Byte7对应的ASCII码";
CM_ SG_ 2417684065 S2P_Cfg10_HW_Ver_Byte8_33 "CSC硬件版本号Byte8对应的ASCII码";
CM_ SG_ 2417684066 S2P_Cfg10_HW_Ver_Byte1_34 "CSC硬件版本号最低字节Byte1对应的ASCII码";
CM_ SG_ 2417684066 S2P_Cfg10_HW_Ver_Byte2_34 "CSC硬件版本号Byte2对应的ASCII码";
CM_ SG_ 2417684066 S2P_Cfg10_HW_Ver_Byte3_34 "CSC硬件版本号Byte3对应的ASCII码";
CM_ SG_ 2417684066 S2P_Cfg10_HW_Ver_Byte4_34 "CSC硬件版本号Byte4对应的ASCII码";
CM_ SG_ 2417684066 S2P_Cfg10_HW_Ver_Byte5_34 "CSC硬件版本号Byte5对应的ASCII码";
CM_ SG_ 2417684066 S2P_Cfg10_HW_Ver_Byte6_34 "CSC硬件版本号Byte6对应的ASCII码";
CM_ SG_ 2417684066 S2P_Cfg10_HW_Ver_Byte7_34 "CSC硬件版本号Byte7对应的ASCII码";
CM_ SG_ 2417684066 S2P_Cfg10_HW_Ver_Byte8_34 "CSC硬件版本号Byte8对应的ASCII码";
CM_ SG_ 2417684067 S2P_Cfg10_HW_Ver_Byte1_35 "CSC硬件版本号最低字节Byte1对应的ASCII码";
CM_ SG_ 2417684067 S2P_Cfg10_HW_Ver_Byte2_35 "CSC硬件版本号Byte2对应的ASCII码";
CM_ SG_ 2417684067 S2P_Cfg10_HW_Ver_Byte3_35 "CSC硬件版本号Byte3对应的ASCII码";
CM_ SG_ 2417684067 S2P_Cfg10_HW_Ver_Byte4_35 "CSC硬件版本号Byte4对应的ASCII码";
CM_ SG_ 2417684067 S2P_Cfg10_HW_Ver_Byte5_35 "CSC硬件版本号Byte5对应的ASCII码";
CM_ SG_ 2417684067 S2P_Cfg10_HW_Ver_Byte6_35 "CSC硬件版本号Byte6对应的ASCII码";
CM_ SG_ 2417684067 S2P_Cfg10_HW_Ver_Byte7_35 "CSC硬件版本号Byte7对应的ASCII码";
CM_ SG_ 2417684067 S2P_Cfg10_HW_Ver_Byte8_35 "CSC硬件版本号Byte8对应的ASCII码";
CM_ SG_ 2417684068 S2P_Cfg10_HW_Ver_Byte1_36 "CSC硬件版本号最低字节Byte1对应的ASCII码";
CM_ SG_ 2417684068 S2P_Cfg10_HW_Ver_Byte2_36 "CSC硬件版本号Byte2对应的ASCII码";
CM_ SG_ 2417684068 S2P_Cfg10_HW_Ver_Byte3_36 "CSC硬件版本号Byte3对应的ASCII码";
CM_ SG_ 2417684068 S2P_Cfg10_HW_Ver_Byte4_36 "CSC硬件版本号Byte4对应的ASCII码";
CM_ SG_ 2417684068 S2P_Cfg10_HW_Ver_Byte5_36 "CSC硬件版本号Byte5对应的ASCII码";
CM_ SG_ 2417684068 S2P_Cfg10_HW_Ver_Byte6_36 "CSC硬件版本号Byte6对应的ASCII码";
CM_ SG_ 2417684068 S2P_Cfg10_HW_Ver_Byte7_36 "CSC硬件版本号Byte7对应的ASCII码";
CM_ SG_ 2417684068 S2P_Cfg10_HW_Ver_Byte8_36 "CSC硬件版本号Byte8对应的ASCII码";
CM_ SG_ 2417684069 S2P_Cfg10_HW_Ver_Byte1_37 "CSC硬件版本号最低字节Byte1对应的ASCII码";
CM_ SG_ 2417684069 S2P_Cfg10_HW_Ver_Byte2_37 "CSC硬件版本号Byte2对应的ASCII码";
CM_ SG_ 2417684069 S2P_Cfg10_HW_Ver_Byte3_37 "CSC硬件版本号Byte3对应的ASCII码";
CM_ SG_ 2417684069 S2P_Cfg10_HW_Ver_Byte4_37 "CSC硬件版本号Byte4对应的ASCII码";
CM_ SG_ 2417684069 S2P_Cfg10_HW_Ver_Byte5_37 "CSC硬件版本号Byte5对应的ASCII码";
CM_ SG_ 2417684069 S2P_Cfg10_HW_Ver_Byte6_37 "CSC硬件版本号Byte6对应的ASCII码";
CM_ SG_ 2417684069 S2P_Cfg10_HW_Ver_Byte7_37 "CSC硬件版本号Byte7对应的ASCII码";
CM_ SG_ 2417684069 S2P_Cfg10_HW_Ver_Byte8_37 "CSC硬件版本号Byte8对应的ASCII码";
CM_ SG_ 2417684070 S2P_Cfg10_HW_Ver_Byte1_38 "CSC硬件版本号最低字节Byte1对应的ASCII码";
CM_ SG_ 2417684070 S2P_Cfg10_HW_Ver_Byte2_38 "CSC硬件版本号Byte2对应的ASCII码";
CM_ SG_ 2417684070 S2P_Cfg10_HW_Ver_Byte3_38 "CSC硬件版本号Byte3对应的ASCII码";
CM_ SG_ 2417684070 S2P_Cfg10_HW_Ver_Byte4_38 "CSC硬件版本号Byte4对应的ASCII码";
CM_ SG_ 2417684070 S2P_Cfg10_HW_Ver_Byte5_38 "CSC硬件版本号Byte5对应的ASCII码";
CM_ SG_ 2417684070 S2P_Cfg10_HW_Ver_Byte6_38 "CSC硬件版本号Byte6对应的ASCII码";
CM_ SG_ 2417684070 S2P_Cfg10_HW_Ver_Byte7_38 "CSC硬件版本号Byte7对应的ASCII码";
CM_ SG_ 2417684070 S2P_Cfg10_HW_Ver_Byte8_38 "CSC硬件版本号Byte8对应的ASCII码";
CM_ SG_ 2417684071 S2P_Cfg10_HW_Ver_Byte1_39 "CSC硬件版本号最低字节Byte1对应的ASCII码";
CM_ SG_ 2417684071 S2P_Cfg10_HW_Ver_Byte2_39 "CSC硬件版本号Byte2对应的ASCII码";
CM_ SG_ 2417684071 S2P_Cfg10_HW_Ver_Byte3_39 "CSC硬件版本号Byte3对应的ASCII码";
CM_ SG_ 2417684071 S2P_Cfg10_HW_Ver_Byte4_39 "CSC硬件版本号Byte4对应的ASCII码";
CM_ SG_ 2417684071 S2P_Cfg10_HW_Ver_Byte5_39 "CSC硬件版本号Byte5对应的ASCII码";
CM_ SG_ 2417684071 S2P_Cfg10_HW_Ver_Byte6_39 "CSC硬件版本号Byte6对应的ASCII码";
CM_ SG_ 2417684071 S2P_Cfg10_HW_Ver_Byte7_39 "CSC硬件版本号Byte7对应的ASCII码";
CM_ SG_ 2417684071 S2P_Cfg10_HW_Ver_Byte8_39 "CSC硬件版本号Byte8对应的ASCII码";
CM_ SG_ 2417684072 S2P_Cfg10_HW_Ver_Byte1_40 "CSC硬件版本号最低字节Byte1对应的ASCII码";
CM_ SG_ 2417684072 S2P_Cfg10_HW_Ver_Byte2_40 "CSC硬件版本号Byte2对应的ASCII码";
CM_ SG_ 2417684072 S2P_Cfg10_HW_Ver_Byte3_40 "CSC硬件版本号Byte3对应的ASCII码";
CM_ SG_ 2417684072 S2P_Cfg10_HW_Ver_Byte4_40 "CSC硬件版本号Byte4对应的ASCII码";
CM_ SG_ 2417684072 S2P_Cfg10_HW_Ver_Byte5_40 "CSC硬件版本号Byte5对应的ASCII码";
CM_ SG_ 2417684072 S2P_Cfg10_HW_Ver_Byte6_40 "CSC硬件版本号Byte6对应的ASCII码";
CM_ SG_ 2417684072 S2P_Cfg10_HW_Ver_Byte7_40 "CSC硬件版本号Byte7对应的ASCII码";
CM_ SG_ 2417684072 S2P_Cfg10_HW_Ver_Byte8_40 "CSC硬件版本号Byte8对应的ASCII码";
CM_ SG_ 2417684073 S2P_Cfg10_HW_Ver_Byte1_41 "CSC硬件版本号最低字节Byte1对应的ASCII码";
CM_ SG_ 2417684073 S2P_Cfg10_HW_Ver_Byte2_41 "CSC硬件版本号Byte2对应的ASCII码";
CM_ SG_ 2417684073 S2P_Cfg10_HW_Ver_Byte3_41 "CSC硬件版本号Byte3对应的ASCII码";
CM_ SG_ 2417684073 S2P_Cfg10_HW_Ver_Byte4_41 "CSC硬件版本号Byte4对应的ASCII码";
CM_ SG_ 2417684073 S2P_Cfg10_HW_Ver_Byte5_41 "CSC硬件版本号Byte5对应的ASCII码";
CM_ SG_ 2417684073 S2P_Cfg10_HW_Ver_Byte6_41 "CSC硬件版本号Byte6对应的ASCII码";
CM_ SG_ 2417684073 S2P_Cfg10_HW_Ver_Byte7_41 "CSC硬件版本号Byte7对应的ASCII码";
CM_ SG_ 2417684073 S2P_Cfg10_HW_Ver_Byte8_41 "CSC硬件版本号Byte8对应的ASCII码";
CM_ SG_ 2417684074 S2P_Cfg10_HW_Ver_Byte1_42 "CSC硬件版本号最低字节Byte1对应的ASCII码";
CM_ SG_ 2417684074 S2P_Cfg10_HW_Ver_Byte2_42 "CSC硬件版本号Byte2对应的ASCII码";
CM_ SG_ 2417684074 S2P_Cfg10_HW_Ver_Byte3_42 "CSC硬件版本号Byte3对应的ASCII码";
CM_ SG_ 2417684074 S2P_Cfg10_HW_Ver_Byte4_42 "CSC硬件版本号Byte4对应的ASCII码";
CM_ SG_ 2417684074 S2P_Cfg10_HW_Ver_Byte5_42 "CSC硬件版本号Byte5对应的ASCII码";
CM_ SG_ 2417684074 S2P_Cfg10_HW_Ver_Byte6_42 "CSC硬件版本号Byte6对应的ASCII码";
CM_ SG_ 2417684074 S2P_Cfg10_HW_Ver_Byte7_42 "CSC硬件版本号Byte7对应的ASCII码";
CM_ SG_ 2417684074 S2P_Cfg10_HW_Ver_Byte8_42 "CSC硬件版本号Byte8对应的ASCII码";
CM_ SG_ 2417684075 S2P_Cfg10_HW_Ver_Byte1_43 "CSC硬件版本号最低字节Byte1对应的ASCII码";
CM_ SG_ 2417684075 S2P_Cfg10_HW_Ver_Byte2_43 "CSC硬件版本号Byte2对应的ASCII码";
CM_ SG_ 2417684075 S2P_Cfg10_HW_Ver_Byte3_43 "CSC硬件版本号Byte3对应的ASCII码";
CM_ SG_ 2417684075 S2P_Cfg10_HW_Ver_Byte4_43 "CSC硬件版本号Byte4对应的ASCII码";
CM_ SG_ 2417684075 S2P_Cfg10_HW_Ver_Byte5_43 "CSC硬件版本号Byte5对应的ASCII码";
CM_ SG_ 2417684075 S2P_Cfg10_HW_Ver_Byte6_43 "CSC硬件版本号Byte6对应的ASCII码";
CM_ SG_ 2417684075 S2P_Cfg10_HW_Ver_Byte7_43 "CSC硬件版本号Byte7对应的ASCII码";
CM_ SG_ 2417684075 S2P_Cfg10_HW_Ver_Byte8_43 "CSC硬件版本号Byte8对应的ASCII码";
CM_ SG_ 2417684076 S2P_Cfg10_HW_Ver_Byte1_44 "CSC硬件版本号最低字节Byte1对应的ASCII码";
CM_ SG_ 2417684076 S2P_Cfg10_HW_Ver_Byte2_44 "CSC硬件版本号Byte2对应的ASCII码";
CM_ SG_ 2417684076 S2P_Cfg10_HW_Ver_Byte3_44 "CSC硬件版本号Byte3对应的ASCII码";
CM_ SG_ 2417684076 S2P_Cfg10_HW_Ver_Byte4_44 "CSC硬件版本号Byte4对应的ASCII码";
CM_ SG_ 2417684076 S2P_Cfg10_HW_Ver_Byte5_44 "CSC硬件版本号Byte5对应的ASCII码";
CM_ SG_ 2417684076 S2P_Cfg10_HW_Ver_Byte6_44 "CSC硬件版本号Byte6对应的ASCII码";
CM_ SG_ 2417684076 S2P_Cfg10_HW_Ver_Byte7_44 "CSC硬件版本号Byte7对应的ASCII码";
CM_ SG_ 2417684076 S2P_Cfg10_HW_Ver_Byte8_44 "CSC硬件版本号Byte8对应的ASCII码";
CM_ SG_ 2417684077 S2P_Cfg10_HW_Ver_Byte1_45 "CSC硬件版本号最低字节Byte1对应的ASCII码";
CM_ SG_ 2417684077 S2P_Cfg10_HW_Ver_Byte2_45 "CSC硬件版本号Byte2对应的ASCII码";
CM_ SG_ 2417684077 S2P_Cfg10_HW_Ver_Byte3_45 "CSC硬件版本号Byte3对应的ASCII码";
CM_ SG_ 2417684077 S2P_Cfg10_HW_Ver_Byte4_45 "CSC硬件版本号Byte4对应的ASCII码";
CM_ SG_ 2417684077 S2P_Cfg10_HW_Ver_Byte5_45 "CSC硬件版本号Byte5对应的ASCII码";
CM_ SG_ 2417684077 S2P_Cfg10_HW_Ver_Byte6_45 "CSC硬件版本号Byte6对应的ASCII码";
CM_ SG_ 2417684077 S2P_Cfg10_HW_Ver_Byte7_45 "CSC硬件版本号Byte7对应的ASCII码";
CM_ SG_ 2417684077 S2P_Cfg10_HW_Ver_Byte8_45 "CSC硬件版本号Byte8对应的ASCII码";
CM_ SG_ 2417684078 S2P_Cfg10_HW_Ver_Byte1_46 "CSC硬件版本号最低字节Byte1对应的ASCII码";
CM_ SG_ 2417684078 S2P_Cfg10_HW_Ver_Byte2_46 "CSC硬件版本号Byte2对应的ASCII码";
CM_ SG_ 2417684078 S2P_Cfg10_HW_Ver_Byte3_46 "CSC硬件版本号Byte3对应的ASCII码";
CM_ SG_ 2417684078 S2P_Cfg10_HW_Ver_Byte4_46 "CSC硬件版本号Byte4对应的ASCII码";
CM_ SG_ 2417684078 S2P_Cfg10_HW_Ver_Byte5_46 "CSC硬件版本号Byte5对应的ASCII码";
CM_ SG_ 2417684078 S2P_Cfg10_HW_Ver_Byte6_46 "CSC硬件版本号Byte6对应的ASCII码";
CM_ SG_ 2417684078 S2P_Cfg10_HW_Ver_Byte7_46 "CSC硬件版本号Byte7对应的ASCII码";
CM_ SG_ 2417684078 S2P_Cfg10_HW_Ver_Byte8_46 "CSC硬件版本号Byte8对应的ASCII码";
CM_ SG_ 2417684079 S2P_Cfg10_HW_Ver_Byte1_47 "CSC硬件版本号最低字节Byte1对应的ASCII码";
CM_ SG_ 2417684079 S2P_Cfg10_HW_Ver_Byte2_47 "CSC硬件版本号Byte2对应的ASCII码";
CM_ SG_ 2417684079 S2P_Cfg10_HW_Ver_Byte3_47 "CSC硬件版本号Byte3对应的ASCII码";
CM_ SG_ 2417684079 S2P_Cfg10_HW_Ver_Byte4_47 "CSC硬件版本号Byte4对应的ASCII码";
CM_ SG_ 2417684079 S2P_Cfg10_HW_Ver_Byte5_47 "CSC硬件版本号Byte5对应的ASCII码";
CM_ SG_ 2417684079 S2P_Cfg10_HW_Ver_Byte6_47 "CSC硬件版本号Byte6对应的ASCII码";
CM_ SG_ 2417684079 S2P_Cfg10_HW_Ver_Byte7_47 "CSC硬件版本号Byte7对应的ASCII码";
CM_ SG_ 2417684079 S2P_Cfg10_HW_Ver_Byte8_47 "CSC硬件版本号Byte8对应的ASCII码";
CM_ SG_ 2417684080 S2P_Cfg10_HW_Ver_Byte1_48 "CSC硬件版本号最低字节Byte1对应的ASCII码";
CM_ SG_ 2417684080 S2P_Cfg10_HW_Ver_Byte2_48 "CSC硬件版本号Byte2对应的ASCII码";
CM_ SG_ 2417684080 S2P_Cfg10_HW_Ver_Byte3_48 "CSC硬件版本号Byte3对应的ASCII码";
CM_ SG_ 2417684080 S2P_Cfg10_HW_Ver_Byte4_48 "CSC硬件版本号Byte4对应的ASCII码";
CM_ SG_ 2417684080 S2P_Cfg10_HW_Ver_Byte5_48 "CSC硬件版本号Byte5对应的ASCII码";
CM_ SG_ 2417684080 S2P_Cfg10_HW_Ver_Byte6_48 "CSC硬件版本号Byte6对应的ASCII码";
CM_ SG_ 2417684080 S2P_Cfg10_HW_Ver_Byte7_48 "CSC硬件版本号Byte7对应的ASCII码";
CM_ SG_ 2417684080 S2P_Cfg10_HW_Ver_Byte8_48 "CSC硬件版本号Byte8对应的ASCII码";
CM_ SG_ 2417684081 S2P_Cfg10_HW_Ver_Byte1_49 "CSC硬件版本号最低字节Byte1对应的ASCII码";
CM_ SG_ 2417684081 S2P_Cfg10_HW_Ver_Byte2_49 "CSC硬件版本号Byte2对应的ASCII码";
CM_ SG_ 2417684081 S2P_Cfg10_HW_Ver_Byte3_49 "CSC硬件版本号Byte3对应的ASCII码";
CM_ SG_ 2417684081 S2P_Cfg10_HW_Ver_Byte4_49 "CSC硬件版本号Byte4对应的ASCII码";
CM_ SG_ 2417684081 S2P_Cfg10_HW_Ver_Byte5_49 "CSC硬件版本号Byte5对应的ASCII码";
CM_ SG_ 2417684081 S2P_Cfg10_HW_Ver_Byte6_49 "CSC硬件版本号Byte6对应的ASCII码";
CM_ SG_ 2417684081 S2P_Cfg10_HW_Ver_Byte7_49 "CSC硬件版本号Byte7对应的ASCII码";
CM_ SG_ 2417684081 S2P_Cfg10_HW_Ver_Byte8_49 "CSC硬件版本号Byte8对应的ASCII码";
CM_ SG_ 2417684082 S2P_Cfg10_HW_Ver_Byte1_50 "CSC硬件版本号最低字节Byte1对应的ASCII码";
CM_ SG_ 2417684082 S2P_Cfg10_HW_Ver_Byte2_50 "CSC硬件版本号Byte2对应的ASCII码";
CM_ SG_ 2417684082 S2P_Cfg10_HW_Ver_Byte3_50 "CSC硬件版本号Byte3对应的ASCII码";
CM_ SG_ 2417684082 S2P_Cfg10_HW_Ver_Byte4_50 "CSC硬件版本号Byte4对应的ASCII码";
CM_ SG_ 2417684082 S2P_Cfg10_HW_Ver_Byte5_50 "CSC硬件版本号Byte5对应的ASCII码";
CM_ SG_ 2417684082 S2P_Cfg10_HW_Ver_Byte6_50 "CSC硬件版本号Byte6对应的ASCII码";
CM_ SG_ 2417684082 S2P_Cfg10_HW_Ver_Byte7_50 "CSC硬件版本号Byte7对应的ASCII码";
CM_ SG_ 2417684082 S2P_Cfg10_HW_Ver_Byte8_50 "CSC硬件版本号Byte8对应的ASCII码";
CM_ SG_ 2417684083 S2P_Cfg10_HW_Ver_Byte1_51 "CSC硬件版本号最低字节Byte1对应的ASCII码";
CM_ SG_ 2417684083 S2P_Cfg10_HW_Ver_Byte2_51 "CSC硬件版本号Byte2对应的ASCII码";
CM_ SG_ 2417684083 S2P_Cfg10_HW_Ver_Byte3_51 "CSC硬件版本号Byte3对应的ASCII码";
CM_ SG_ 2417684083 S2P_Cfg10_HW_Ver_Byte4_51 "CSC硬件版本号Byte4对应的ASCII码";
CM_ SG_ 2417684083 S2P_Cfg10_HW_Ver_Byte5_51 "CSC硬件版本号Byte5对应的ASCII码";
CM_ SG_ 2417684083 S2P_Cfg10_HW_Ver_Byte6_51 "CSC硬件版本号Byte6对应的ASCII码";
CM_ SG_ 2417684083 S2P_Cfg10_HW_Ver_Byte7_51 "CSC硬件版本号Byte7对应的ASCII码";
CM_ SG_ 2417684083 S2P_Cfg10_HW_Ver_Byte8_51 "CSC硬件版本号Byte8对应的ASCII码";
CM_ SG_ 2417684084 S2P_Cfg10_HW_Ver_Byte1_52 "CSC硬件版本号最低字节Byte1对应的ASCII码";
CM_ SG_ 2417684084 S2P_Cfg10_HW_Ver_Byte2_52 "CSC硬件版本号Byte2对应的ASCII码";
CM_ SG_ 2417684084 S2P_Cfg10_HW_Ver_Byte3_52 "CSC硬件版本号Byte3对应的ASCII码";
CM_ SG_ 2417684084 S2P_Cfg10_HW_Ver_Byte4_52 "CSC硬件版本号Byte4对应的ASCII码";
CM_ SG_ 2417684084 S2P_Cfg10_HW_Ver_Byte5_52 "CSC硬件版本号Byte5对应的ASCII码";
CM_ SG_ 2417684084 S2P_Cfg10_HW_Ver_Byte6_52 "CSC硬件版本号Byte6对应的ASCII码";
CM_ SG_ 2417684084 S2P_Cfg10_HW_Ver_Byte7_52 "CSC硬件版本号Byte7对应的ASCII码";
CM_ SG_ 2417684084 S2P_Cfg10_HW_Ver_Byte8_52 "CSC硬件版本号Byte8对应的ASCII码";
CM_ SG_ 2417684085 S2P_Cfg10_HW_Ver_Byte1_53 "CSC硬件版本号最低字节Byte1对应的ASCII码";
CM_ SG_ 2417684085 S2P_Cfg10_HW_Ver_Byte2_53 "CSC硬件版本号Byte2对应的ASCII码";
CM_ SG_ 2417684085 S2P_Cfg10_HW_Ver_Byte3_53 "CSC硬件版本号Byte3对应的ASCII码";
CM_ SG_ 2417684085 S2P_Cfg10_HW_Ver_Byte4_53 "CSC硬件版本号Byte4对应的ASCII码";
CM_ SG_ 2417684085 S2P_Cfg10_HW_Ver_Byte5_53 "CSC硬件版本号Byte5对应的ASCII码";
CM_ SG_ 2417684085 S2P_Cfg10_HW_Ver_Byte6_53 "CSC硬件版本号Byte6对应的ASCII码";
CM_ SG_ 2417684085 S2P_Cfg10_HW_Ver_Byte7_53 "CSC硬件版本号Byte7对应的ASCII码";
CM_ SG_ 2417684085 S2P_Cfg10_HW_Ver_Byte8_53 "CSC硬件版本号Byte8对应的ASCII码";
CM_ SG_ 2417684086 S2P_Cfg10_HW_Ver_Byte1_54 "CSC硬件版本号最低字节Byte1对应的ASCII码";
CM_ SG_ 2417684086 S2P_Cfg10_HW_Ver_Byte2_54 "CSC硬件版本号Byte2对应的ASCII码";
CM_ SG_ 2417684086 S2P_Cfg10_HW_Ver_Byte3_54 "CSC硬件版本号Byte3对应的ASCII码";
CM_ SG_ 2417684086 S2P_Cfg10_HW_Ver_Byte4_54 "CSC硬件版本号Byte4对应的ASCII码";
CM_ SG_ 2417684086 S2P_Cfg10_HW_Ver_Byte5_54 "CSC硬件版本号Byte5对应的ASCII码";
CM_ SG_ 2417684086 S2P_Cfg10_HW_Ver_Byte6_54 "CSC硬件版本号Byte6对应的ASCII码";
CM_ SG_ 2417684086 S2P_Cfg10_HW_Ver_Byte7_54 "CSC硬件版本号Byte7对应的ASCII码";
CM_ SG_ 2417684086 S2P_Cfg10_HW_Ver_Byte8_54 "CSC硬件版本号Byte8对应的ASCII码";
CM_ SG_ 2417684087 S2P_Cfg10_HW_Ver_Byte1_55 "CSC硬件版本号最低字节Byte1对应的ASCII码";
CM_ SG_ 2417684087 S2P_Cfg10_HW_Ver_Byte2_55 "CSC硬件版本号Byte2对应的ASCII码";
CM_ SG_ 2417684087 S2P_Cfg10_HW_Ver_Byte3_55 "CSC硬件版本号Byte3对应的ASCII码";
CM_ SG_ 2417684087 S2P_Cfg10_HW_Ver_Byte4_55 "CSC硬件版本号Byte4对应的ASCII码";
CM_ SG_ 2417684087 S2P_Cfg10_HW_Ver_Byte5_55 "CSC硬件版本号Byte5对应的ASCII码";
CM_ SG_ 2417684087 S2P_Cfg10_HW_Ver_Byte6_55 "CSC硬件版本号Byte6对应的ASCII码";
CM_ SG_ 2417684087 S2P_Cfg10_HW_Ver_Byte7_55 "CSC硬件版本号Byte7对应的ASCII码";
CM_ SG_ 2417684087 S2P_Cfg10_HW_Ver_Byte8_55 "CSC硬件版本号Byte8对应的ASCII码";
CM_ SG_ 2417684088 S2P_Cfg10_HW_Ver_Byte1_56 "CSC硬件版本号最低字节Byte1对应的ASCII码";
CM_ SG_ 2417684088 S2P_Cfg10_HW_Ver_Byte2_56 "CSC硬件版本号Byte2对应的ASCII码";
CM_ SG_ 2417684088 S2P_Cfg10_HW_Ver_Byte3_56 "CSC硬件版本号Byte3对应的ASCII码";
CM_ SG_ 2417684088 S2P_Cfg10_HW_Ver_Byte4_56 "CSC硬件版本号Byte4对应的ASCII码";
CM_ SG_ 2417684088 S2P_Cfg10_HW_Ver_Byte5_56 "CSC硬件版本号Byte5对应的ASCII码";
CM_ SG_ 2417684088 S2P_Cfg10_HW_Ver_Byte6_56 "CSC硬件版本号Byte6对应的ASCII码";
CM_ SG_ 2417684088 S2P_Cfg10_HW_Ver_Byte7_56 "CSC硬件版本号Byte7对应的ASCII码";
CM_ SG_ 2417684088 S2P_Cfg10_HW_Ver_Byte8_56 "CSC硬件版本号Byte8对应的ASCII码";
CM_ SG_ 2417684089 S2P_Cfg10_HW_Ver_Byte1_57 "CSC硬件版本号最低字节Byte1对应的ASCII码";
CM_ SG_ 2417684089 S2P_Cfg10_HW_Ver_Byte2_57 "CSC硬件版本号Byte2对应的ASCII码";
CM_ SG_ 2417684089 S2P_Cfg10_HW_Ver_Byte3_57 "CSC硬件版本号Byte3对应的ASCII码";
CM_ SG_ 2417684089 S2P_Cfg10_HW_Ver_Byte4_57 "CSC硬件版本号Byte4对应的ASCII码";
CM_ SG_ 2417684089 S2P_Cfg10_HW_Ver_Byte5_57 "CSC硬件版本号Byte5对应的ASCII码";
CM_ SG_ 2417684089 S2P_Cfg10_HW_Ver_Byte6_57 "CSC硬件版本号Byte6对应的ASCII码";
CM_ SG_ 2417684089 S2P_Cfg10_HW_Ver_Byte7_57 "CSC硬件版本号Byte7对应的ASCII码";
CM_ SG_ 2417684089 S2P_Cfg10_HW_Ver_Byte8_57 "CSC硬件版本号Byte8对应的ASCII码";
CM_ SG_ 2417684090 S2P_Cfg10_HW_Ver_Byte1_58 "CSC硬件版本号最低字节Byte1对应的ASCII码";
CM_ SG_ 2417684090 S2P_Cfg10_HW_Ver_Byte2_58 "CSC硬件版本号Byte2对应的ASCII码";
CM_ SG_ 2417684090 S2P_Cfg10_HW_Ver_Byte3_58 "CSC硬件版本号Byte3对应的ASCII码";
CM_ SG_ 2417684090 S2P_Cfg10_HW_Ver_Byte4_58 "CSC硬件版本号Byte4对应的ASCII码";
CM_ SG_ 2417684090 S2P_Cfg10_HW_Ver_Byte5_58 "CSC硬件版本号Byte5对应的ASCII码";
CM_ SG_ 2417684090 S2P_Cfg10_HW_Ver_Byte6_58 "CSC硬件版本号Byte6对应的ASCII码";
CM_ SG_ 2417684090 S2P_Cfg10_HW_Ver_Byte7_58 "CSC硬件版本号Byte7对应的ASCII码";
CM_ SG_ 2417684090 S2P_Cfg10_HW_Ver_Byte8_58 "CSC硬件版本号Byte8对应的ASCII码";
CM_ SG_ 2417684091 S2P_Cfg10_HW_Ver_Byte1_59 "CSC硬件版本号最低字节Byte1对应的ASCII码";
CM_ SG_ 2417684091 S2P_Cfg10_HW_Ver_Byte2_59 "CSC硬件版本号Byte2对应的ASCII码";
CM_ SG_ 2417684091 S2P_Cfg10_HW_Ver_Byte3_59 "CSC硬件版本号Byte3对应的ASCII码";
CM_ SG_ 2417684091 S2P_Cfg10_HW_Ver_Byte4_59 "CSC硬件版本号Byte4对应的ASCII码";
CM_ SG_ 2417684091 S2P_Cfg10_HW_Ver_Byte5_59 "CSC硬件版本号Byte5对应的ASCII码";
CM_ SG_ 2417684091 S2P_Cfg10_HW_Ver_Byte6_59 "CSC硬件版本号Byte6对应的ASCII码";
CM_ SG_ 2417684091 S2P_Cfg10_HW_Ver_Byte7_59 "CSC硬件版本号Byte7对应的ASCII码";
CM_ SG_ 2417684091 S2P_Cfg10_HW_Ver_Byte8_59 "CSC硬件版本号Byte8对应的ASCII码";
CM_ SG_ 2417684092 S2P_Cfg10_HW_Ver_Byte1_60 "CSC硬件版本号最低字节Byte1对应的ASCII码";
CM_ SG_ 2417684092 S2P_Cfg10_HW_Ver_Byte2_60 "CSC硬件版本号Byte2对应的ASCII码";
CM_ SG_ 2417684092 S2P_Cfg10_HW_Ver_Byte3_60 "CSC硬件版本号Byte3对应的ASCII码";
CM_ SG_ 2417684092 S2P_Cfg10_HW_Ver_Byte4_60 "CSC硬件版本号Byte4对应的ASCII码";
CM_ SG_ 2417684092 S2P_Cfg10_HW_Ver_Byte5_60 "CSC硬件版本号Byte5对应的ASCII码";
CM_ SG_ 2417684092 S2P_Cfg10_HW_Ver_Byte6_60 "CSC硬件版本号Byte6对应的ASCII码";
CM_ SG_ 2417684092 S2P_Cfg10_HW_Ver_Byte7_60 "CSC硬件版本号Byte7对应的ASCII码";
CM_ SG_ 2417684092 S2P_Cfg10_HW_Ver_Byte8_60 "CSC硬件版本号Byte8对应的ASCII码";
CM_ SG_ 2417684093 S2P_Cfg10_HW_Ver_Byte1_61 "CSC硬件版本号最低字节Byte1对应的ASCII码";
CM_ SG_ 2417684093 S2P_Cfg10_HW_Ver_Byte2_61 "CSC硬件版本号Byte2对应的ASCII码";
CM_ SG_ 2417684093 S2P_Cfg10_HW_Ver_Byte3_61 "CSC硬件版本号Byte3对应的ASCII码";
CM_ SG_ 2417684093 S2P_Cfg10_HW_Ver_Byte4_61 "CSC硬件版本号Byte4对应的ASCII码";
CM_ SG_ 2417684093 S2P_Cfg10_HW_Ver_Byte5_61 "CSC硬件版本号Byte5对应的ASCII码";
CM_ SG_ 2417684093 S2P_Cfg10_HW_Ver_Byte6_61 "CSC硬件版本号Byte6对应的ASCII码";
CM_ SG_ 2417684093 S2P_Cfg10_HW_Ver_Byte7_61 "CSC硬件版本号Byte7对应的ASCII码";
CM_ SG_ 2417684093 S2P_Cfg10_HW_Ver_Byte8_61 "CSC硬件版本号Byte8对应的ASCII码";
CM_ SG_ 2417684094 S2P_Cfg10_HW_Ver_Byte1_62 "CSC硬件版本号最低字节Byte1对应的ASCII码";
CM_ SG_ 2417684094 S2P_Cfg10_HW_Ver_Byte2_62 "CSC硬件版本号Byte2对应的ASCII码";
CM_ SG_ 2417684094 S2P_Cfg10_HW_Ver_Byte3_62 "CSC硬件版本号Byte3对应的ASCII码";
CM_ SG_ 2417684094 S2P_Cfg10_HW_Ver_Byte4_62 "CSC硬件版本号Byte4对应的ASCII码";
CM_ SG_ 2417684094 S2P_Cfg10_HW_Ver_Byte5_62 "CSC硬件版本号Byte5对应的ASCII码";
CM_ SG_ 2417684094 S2P_Cfg10_HW_Ver_Byte6_62 "CSC硬件版本号Byte6对应的ASCII码";
CM_ SG_ 2417684094 S2P_Cfg10_HW_Ver_Byte7_62 "CSC硬件版本号Byte7对应的ASCII码";
CM_ SG_ 2417684094 S2P_Cfg10_HW_Ver_Byte8_62 "CSC硬件版本号Byte8对应的ASCII码";
CM_ SG_ 2417684095 S2P_Cfg10_HW_Ver_Byte1_63 "CSC硬件版本号最低字节Byte1对应的ASCII码";
CM_ SG_ 2417684095 S2P_Cfg10_HW_Ver_Byte2_63 "CSC硬件版本号Byte2对应的ASCII码";
CM_ SG_ 2417684095 S2P_Cfg10_HW_Ver_Byte3_63 "CSC硬件版本号Byte3对应的ASCII码";
CM_ SG_ 2417684095 S2P_Cfg10_HW_Ver_Byte4_63 "CSC硬件版本号Byte4对应的ASCII码";
CM_ SG_ 2417684095 S2P_Cfg10_HW_Ver_Byte5_63 "CSC硬件版本号Byte5对应的ASCII码";
CM_ SG_ 2417684095 S2P_Cfg10_HW_Ver_Byte6_63 "CSC硬件版本号Byte6对应的ASCII码";
CM_ SG_ 2417684095 S2P_Cfg10_HW_Ver_Byte7_63 "CSC硬件版本号Byte7对应的ASCII码";
CM_ SG_ 2417684095 S2P_Cfg10_HW_Ver_Byte8_63 "CSC硬件版本号Byte8对应的ASCII码";
CM_ SG_ 2417749569 S2P_Cfg11_HW_Ver_Byte9_01 "CSC硬件版本号Byte9对应的ASCII码";
CM_ SG_ 2417749569 S2P_Cfg11_HW_Ver_Byte10_01 "CSC硬件版本号Byte10对应的ASCII码";
CM_ SG_ 2417749569 S2P_Cfg11_HW_Ver_Byte11_01 "CSC硬件版本号Byte11对应的ASCII码";
CM_ SG_ 2417749569 S2P_Cfg11_HW_Ver_Byte12_01 "CSC硬件版本号Byte12对应的ASCII码";
CM_ SG_ 2417749569 S2P_Cfg11_HW_Ver_Byte13_01 "CSC硬件版本号Byte13对应的ASCII码";
CM_ SG_ 2417749569 S2P_Cfg11_HW_Ver_Byte14_01 "CSC硬件版本号Byte14对应的ASCII码";
CM_ SG_ 2417749569 S2P_Cfg11_HW_Ver_Byte15_01 "CSC硬件版本号Byte15对应的ASCII码";
CM_ SG_ 2417749569 S2P_Cfg11_HW_Ver_Byte16_01 "CSC硬件版本号最高字节Byte16对应的ASCII码";
CM_ SG_ 2417749570 S2P_Cfg11_HW_Ver_Byte9_02 "CSC硬件版本号Byte9对应的ASCII码";
CM_ SG_ 2417749570 S2P_Cfg11_HW_Ver_Byte10_02 "CSC硬件版本号Byte10对应的ASCII码";
CM_ SG_ 2417749570 S2P_Cfg11_HW_Ver_Byte11_02 "CSC硬件版本号Byte11对应的ASCII码";
CM_ SG_ 2417749570 S2P_Cfg11_HW_Ver_Byte12_02 "CSC硬件版本号Byte12对应的ASCII码";
CM_ SG_ 2417749570 S2P_Cfg11_HW_Ver_Byte13_02 "CSC硬件版本号Byte13对应的ASCII码";
CM_ SG_ 2417749570 S2P_Cfg11_HW_Ver_Byte14_02 "CSC硬件版本号Byte14对应的ASCII码";
CM_ SG_ 2417749570 S2P_Cfg11_HW_Ver_Byte15_02 "CSC硬件版本号Byte15对应的ASCII码";
CM_ SG_ 2417749570 S2P_Cfg11_HW_Ver_Byte16_02 "CSC硬件版本号最高字节Byte16对应的ASCII码";
CM_ SG_ 2417749571 S2P_Cfg11_HW_Ver_Byte9_03 "CSC硬件版本号Byte9对应的ASCII码";
CM_ SG_ 2417749571 S2P_Cfg11_HW_Ver_Byte10_03 "CSC硬件版本号Byte10对应的ASCII码";
CM_ SG_ 2417749571 S2P_Cfg11_HW_Ver_Byte11_03 "CSC硬件版本号Byte11对应的ASCII码";
CM_ SG_ 2417749571 S2P_Cfg11_HW_Ver_Byte12_03 "CSC硬件版本号Byte12对应的ASCII码";
CM_ SG_ 2417749571 S2P_Cfg11_HW_Ver_Byte13_03 "CSC硬件版本号Byte13对应的ASCII码";
CM_ SG_ 2417749571 S2P_Cfg11_HW_Ver_Byte14_03 "CSC硬件版本号Byte14对应的ASCII码";
CM_ SG_ 2417749571 S2P_Cfg11_HW_Ver_Byte15_03 "CSC硬件版本号Byte15对应的ASCII码";
CM_ SG_ 2417749571 S2P_Cfg11_HW_Ver_Byte16_03 "CSC硬件版本号最高字节Byte16对应的ASCII码";
CM_ SG_ 2417749572 S2P_Cfg11_HW_Ver_Byte9_04 "CSC硬件版本号Byte9对应的ASCII码";
CM_ SG_ 2417749572 S2P_Cfg11_HW_Ver_Byte10_04 "CSC硬件版本号Byte10对应的ASCII码";
CM_ SG_ 2417749572 S2P_Cfg11_HW_Ver_Byte11_04 "CSC硬件版本号Byte11对应的ASCII码";
CM_ SG_ 2417749572 S2P_Cfg11_HW_Ver_Byte12_04 "CSC硬件版本号Byte12对应的ASCII码";
CM_ SG_ 2417749572 S2P_Cfg11_HW_Ver_Byte13_04 "CSC硬件版本号Byte13对应的ASCII码";
CM_ SG_ 2417749572 S2P_Cfg11_HW_Ver_Byte14_04 "CSC硬件版本号Byte14对应的ASCII码";
CM_ SG_ 2417749572 S2P_Cfg11_HW_Ver_Byte15_04 "CSC硬件版本号Byte15对应的ASCII码";
CM_ SG_ 2417749572 S2P_Cfg11_HW_Ver_Byte16_04 "CSC硬件版本号最高字节Byte16对应的ASCII码";
CM_ SG_ 2417749573 S2P_Cfg11_HW_Ver_Byte9_05 "CSC硬件版本号Byte9对应的ASCII码";
CM_ SG_ 2417749573 S2P_Cfg11_HW_Ver_Byte10_05 "CSC硬件版本号Byte10对应的ASCII码";
CM_ SG_ 2417749573 S2P_Cfg11_HW_Ver_Byte11_05 "CSC硬件版本号Byte11对应的ASCII码";
CM_ SG_ 2417749573 S2P_Cfg11_HW_Ver_Byte12_05 "CSC硬件版本号Byte12对应的ASCII码";
CM_ SG_ 2417749573 S2P_Cfg11_HW_Ver_Byte13_05 "CSC硬件版本号Byte13对应的ASCII码";
CM_ SG_ 2417749573 S2P_Cfg11_HW_Ver_Byte14_05 "CSC硬件版本号Byte14对应的ASCII码";
CM_ SG_ 2417749573 S2P_Cfg11_HW_Ver_Byte15_05 "CSC硬件版本号Byte15对应的ASCII码";
CM_ SG_ 2417749573 S2P_Cfg11_HW_Ver_Byte16_05 "CSC硬件版本号最高字节Byte16对应的ASCII码";
CM_ SG_ 2417749574 S2P_Cfg11_HW_Ver_Byte9_06 "CSC硬件版本号Byte9对应的ASCII码";
CM_ SG_ 2417749574 S2P_Cfg11_HW_Ver_Byte10_06 "CSC硬件版本号Byte10对应的ASCII码";
CM_ SG_ 2417749574 S2P_Cfg11_HW_Ver_Byte11_06 "CSC硬件版本号Byte11对应的ASCII码";
CM_ SG_ 2417749574 S2P_Cfg11_HW_Ver_Byte12_06 "CSC硬件版本号Byte12对应的ASCII码";
CM_ SG_ 2417749574 S2P_Cfg11_HW_Ver_Byte13_06 "CSC硬件版本号Byte13对应的ASCII码";
CM_ SG_ 2417749574 S2P_Cfg11_HW_Ver_Byte14_06 "CSC硬件版本号Byte14对应的ASCII码";
CM_ SG_ 2417749574 S2P_Cfg11_HW_Ver_Byte15_06 "CSC硬件版本号Byte15对应的ASCII码";
CM_ SG_ 2417749574 S2P_Cfg11_HW_Ver_Byte16_06 "CSC硬件版本号最高字节Byte16对应的ASCII码";
CM_ SG_ 2417749575 S2P_Cfg11_HW_Ver_Byte9_07 "CSC硬件版本号Byte9对应的ASCII码";
CM_ SG_ 2417749575 S2P_Cfg11_HW_Ver_Byte10_07 "CSC硬件版本号Byte10对应的ASCII码";
CM_ SG_ 2417749575 S2P_Cfg11_HW_Ver_Byte11_07 "CSC硬件版本号Byte11对应的ASCII码";
CM_ SG_ 2417749575 S2P_Cfg11_HW_Ver_Byte12_07 "CSC硬件版本号Byte12对应的ASCII码";
CM_ SG_ 2417749575 S2P_Cfg11_HW_Ver_Byte13_07 "CSC硬件版本号Byte13对应的ASCII码";
CM_ SG_ 2417749575 S2P_Cfg11_HW_Ver_Byte14_07 "CSC硬件版本号Byte14对应的ASCII码";
CM_ SG_ 2417749575 S2P_Cfg11_HW_Ver_Byte15_07 "CSC硬件版本号Byte15对应的ASCII码";
CM_ SG_ 2417749575 S2P_Cfg11_HW_Ver_Byte16_07 "CSC硬件版本号最高字节Byte16对应的ASCII码";
CM_ SG_ 2417749576 S2P_Cfg11_HW_Ver_Byte9_08 "CSC硬件版本号Byte9对应的ASCII码";
CM_ SG_ 2417749576 S2P_Cfg11_HW_Ver_Byte10_08 "CSC硬件版本号Byte10对应的ASCII码";
CM_ SG_ 2417749576 S2P_Cfg11_HW_Ver_Byte11_08 "CSC硬件版本号Byte11对应的ASCII码";
CM_ SG_ 2417749576 S2P_Cfg11_HW_Ver_Byte12_08 "CSC硬件版本号Byte12对应的ASCII码";
CM_ SG_ 2417749576 S2P_Cfg11_HW_Ver_Byte13_08 "CSC硬件版本号Byte13对应的ASCII码";
CM_ SG_ 2417749576 S2P_Cfg11_HW_Ver_Byte14_08 "CSC硬件版本号Byte14对应的ASCII码";
CM_ SG_ 2417749576 S2P_Cfg11_HW_Ver_Byte15_08 "CSC硬件版本号Byte15对应的ASCII码";
CM_ SG_ 2417749576 S2P_Cfg11_HW_Ver_Byte16_08 "CSC硬件版本号最高字节Byte16对应的ASCII码";
CM_ SG_ 2417749577 S2P_Cfg11_HW_Ver_Byte9_09 "CSC硬件版本号Byte9对应的ASCII码";
CM_ SG_ 2417749577 S2P_Cfg11_HW_Ver_Byte10_09 "CSC硬件版本号Byte10对应的ASCII码";
CM_ SG_ 2417749577 S2P_Cfg11_HW_Ver_Byte11_09 "CSC硬件版本号Byte11对应的ASCII码";
CM_ SG_ 2417749577 S2P_Cfg11_HW_Ver_Byte12_09 "CSC硬件版本号Byte12对应的ASCII码";
CM_ SG_ 2417749577 S2P_Cfg11_HW_Ver_Byte13_09 "CSC硬件版本号Byte13对应的ASCII码";
CM_ SG_ 2417749577 S2P_Cfg11_HW_Ver_Byte14_09 "CSC硬件版本号Byte14对应的ASCII码";
CM_ SG_ 2417749577 S2P_Cfg11_HW_Ver_Byte15_09 "CSC硬件版本号Byte15对应的ASCII码";
CM_ SG_ 2417749577 S2P_Cfg11_HW_Ver_Byte16_09 "CSC硬件版本号最高字节Byte16对应的ASCII码";
CM_ SG_ 2417749578 S2P_Cfg11_HW_Ver_Byte9_10 "CSC硬件版本号Byte9对应的ASCII码";
CM_ SG_ 2417749578 S2P_Cfg11_HW_Ver_Byte10_10 "CSC硬件版本号Byte10对应的ASCII码";
CM_ SG_ 2417749578 S2P_Cfg11_HW_Ver_Byte11_10 "CSC硬件版本号Byte11对应的ASCII码";
CM_ SG_ 2417749578 S2P_Cfg11_HW_Ver_Byte12_10 "CSC硬件版本号Byte12对应的ASCII码";
CM_ SG_ 2417749578 S2P_Cfg11_HW_Ver_Byte13_10 "CSC硬件版本号Byte13对应的ASCII码";
CM_ SG_ 2417749578 S2P_Cfg11_HW_Ver_Byte14_10 "CSC硬件版本号Byte14对应的ASCII码";
CM_ SG_ 2417749578 S2P_Cfg11_HW_Ver_Byte15_10 "CSC硬件版本号Byte15对应的ASCII码";
CM_ SG_ 2417749578 S2P_Cfg11_HW_Ver_Byte16_10 "CSC硬件版本号最高字节Byte16对应的ASCII码";
CM_ SG_ 2417749579 S2P_Cfg11_HW_Ver_Byte9_11 "CSC硬件版本号Byte9对应的ASCII码";
CM_ SG_ 2417749579 S2P_Cfg11_HW_Ver_Byte10_11 "CSC硬件版本号Byte10对应的ASCII码";
CM_ SG_ 2417749579 S2P_Cfg11_HW_Ver_Byte11_11 "CSC硬件版本号Byte11对应的ASCII码";
CM_ SG_ 2417749579 S2P_Cfg11_HW_Ver_Byte12_11 "CSC硬件版本号Byte12对应的ASCII码";
CM_ SG_ 2417749579 S2P_Cfg11_HW_Ver_Byte13_11 "CSC硬件版本号Byte13对应的ASCII码";
CM_ SG_ 2417749579 S2P_Cfg11_HW_Ver_Byte14_11 "CSC硬件版本号Byte14对应的ASCII码";
CM_ SG_ 2417749579 S2P_Cfg11_HW_Ver_Byte15_11 "CSC硬件版本号Byte15对应的ASCII码";
CM_ SG_ 2417749579 S2P_Cfg11_HW_Ver_Byte16_11 "CSC硬件版本号最高字节Byte16对应的ASCII码";
CM_ SG_ 2417749580 S2P_Cfg11_HW_Ver_Byte9_12 "CSC硬件版本号Byte9对应的ASCII码";
CM_ SG_ 2417749580 S2P_Cfg11_HW_Ver_Byte10_12 "CSC硬件版本号Byte10对应的ASCII码";
CM_ SG_ 2417749580 S2P_Cfg11_HW_Ver_Byte11_12 "CSC硬件版本号Byte11对应的ASCII码";
CM_ SG_ 2417749580 S2P_Cfg11_HW_Ver_Byte12_12 "CSC硬件版本号Byte12对应的ASCII码";
CM_ SG_ 2417749580 S2P_Cfg11_HW_Ver_Byte13_12 "CSC硬件版本号Byte13对应的ASCII码";
CM_ SG_ 2417749580 S2P_Cfg11_HW_Ver_Byte14_12 "CSC硬件版本号Byte14对应的ASCII码";
CM_ SG_ 2417749580 S2P_Cfg11_HW_Ver_Byte15_12 "CSC硬件版本号Byte15对应的ASCII码";
CM_ SG_ 2417749580 S2P_Cfg11_HW_Ver_Byte16_12 "CSC硬件版本号最高字节Byte16对应的ASCII码";
CM_ SG_ 2417749581 S2P_Cfg11_HW_Ver_Byte9_13 "CSC硬件版本号Byte9对应的ASCII码";
CM_ SG_ 2417749581 S2P_Cfg11_HW_Ver_Byte10_13 "CSC硬件版本号Byte10对应的ASCII码";
CM_ SG_ 2417749581 S2P_Cfg11_HW_Ver_Byte11_13 "CSC硬件版本号Byte11对应的ASCII码";
CM_ SG_ 2417749581 S2P_Cfg11_HW_Ver_Byte12_13 "CSC硬件版本号Byte12对应的ASCII码";
CM_ SG_ 2417749581 S2P_Cfg11_HW_Ver_Byte13_13 "CSC硬件版本号Byte13对应的ASCII码";
CM_ SG_ 2417749581 S2P_Cfg11_HW_Ver_Byte14_13 "CSC硬件版本号Byte14对应的ASCII码";
CM_ SG_ 2417749581 S2P_Cfg11_HW_Ver_Byte15_13 "CSC硬件版本号Byte15对应的ASCII码";
CM_ SG_ 2417749581 S2P_Cfg11_HW_Ver_Byte16_13 "CSC硬件版本号最高字节Byte16对应的ASCII码";
CM_ SG_ 2417749582 S2P_Cfg11_HW_Ver_Byte9_14 "CSC硬件版本号Byte9对应的ASCII码";
CM_ SG_ 2417749582 S2P_Cfg11_HW_Ver_Byte10_14 "CSC硬件版本号Byte10对应的ASCII码";
CM_ SG_ 2417749582 S2P_Cfg11_HW_Ver_Byte11_14 "CSC硬件版本号Byte11对应的ASCII码";
CM_ SG_ 2417749582 S2P_Cfg11_HW_Ver_Byte12_14 "CSC硬件版本号Byte12对应的ASCII码";
CM_ SG_ 2417749582 S2P_Cfg11_HW_Ver_Byte13_14 "CSC硬件版本号Byte13对应的ASCII码";
CM_ SG_ 2417749582 S2P_Cfg11_HW_Ver_Byte14_14 "CSC硬件版本号Byte14对应的ASCII码";
CM_ SG_ 2417749582 S2P_Cfg11_HW_Ver_Byte15_14 "CSC硬件版本号Byte15对应的ASCII码";
CM_ SG_ 2417749582 S2P_Cfg11_HW_Ver_Byte16_14 "CSC硬件版本号最高字节Byte16对应的ASCII码";
CM_ SG_ 2417749583 S2P_Cfg11_HW_Ver_Byte9_15 "CSC硬件版本号Byte9对应的ASCII码";
CM_ SG_ 2417749583 S2P_Cfg11_HW_Ver_Byte10_15 "CSC硬件版本号Byte10对应的ASCII码";
CM_ SG_ 2417749583 S2P_Cfg11_HW_Ver_Byte11_15 "CSC硬件版本号Byte11对应的ASCII码";
CM_ SG_ 2417749583 S2P_Cfg11_HW_Ver_Byte12_15 "CSC硬件版本号Byte12对应的ASCII码";
CM_ SG_ 2417749583 S2P_Cfg11_HW_Ver_Byte13_15 "CSC硬件版本号Byte13对应的ASCII码";
CM_ SG_ 2417749583 S2P_Cfg11_HW_Ver_Byte14_15 "CSC硬件版本号Byte14对应的ASCII码";
CM_ SG_ 2417749583 S2P_Cfg11_HW_Ver_Byte15_15 "CSC硬件版本号Byte15对应的ASCII码";
CM_ SG_ 2417749583 S2P_Cfg11_HW_Ver_Byte16_15 "CSC硬件版本号最高字节Byte16对应的ASCII码";
CM_ SG_ 2417749584 S2P_Cfg11_HW_Ver_Byte9_16 "CSC硬件版本号Byte9对应的ASCII码";
CM_ SG_ 2417749584 S2P_Cfg11_HW_Ver_Byte10_16 "CSC硬件版本号Byte10对应的ASCII码";
CM_ SG_ 2417749584 S2P_Cfg11_HW_Ver_Byte11_16 "CSC硬件版本号Byte11对应的ASCII码";
CM_ SG_ 2417749584 S2P_Cfg11_HW_Ver_Byte12_16 "CSC硬件版本号Byte12对应的ASCII码";
CM_ SG_ 2417749584 S2P_Cfg11_HW_Ver_Byte13_16 "CSC硬件版本号Byte13对应的ASCII码";
CM_ SG_ 2417749584 S2P_Cfg11_HW_Ver_Byte14_16 "CSC硬件版本号Byte14对应的ASCII码";
CM_ SG_ 2417749584 S2P_Cfg11_HW_Ver_Byte15_16 "CSC硬件版本号Byte15对应的ASCII码";
CM_ SG_ 2417749584 S2P_Cfg11_HW_Ver_Byte16_16 "CSC硬件版本号最高字节Byte16对应的ASCII码";
CM_ SG_ 2417749585 S2P_Cfg11_HW_Ver_Byte9_17 "CSC硬件版本号Byte9对应的ASCII码";
CM_ SG_ 2417749585 S2P_Cfg11_HW_Ver_Byte10_17 "CSC硬件版本号Byte10对应的ASCII码";
CM_ SG_ 2417749585 S2P_Cfg11_HW_Ver_Byte11_17 "CSC硬件版本号Byte11对应的ASCII码";
CM_ SG_ 2417749585 S2P_Cfg11_HW_Ver_Byte12_17 "CSC硬件版本号Byte12对应的ASCII码";
CM_ SG_ 2417749585 S2P_Cfg11_HW_Ver_Byte13_17 "CSC硬件版本号Byte13对应的ASCII码";
CM_ SG_ 2417749585 S2P_Cfg11_HW_Ver_Byte14_17 "CSC硬件版本号Byte14对应的ASCII码";
CM_ SG_ 2417749585 S2P_Cfg11_HW_Ver_Byte15_17 "CSC硬件版本号Byte15对应的ASCII码";
CM_ SG_ 2417749585 S2P_Cfg11_HW_Ver_Byte16_17 "CSC硬件版本号最高字节Byte16对应的ASCII码";
CM_ SG_ 2417749586 S2P_Cfg11_HW_Ver_Byte9_18 "CSC硬件版本号Byte9对应的ASCII码";
CM_ SG_ 2417749586 S2P_Cfg11_HW_Ver_Byte10_18 "CSC硬件版本号Byte10对应的ASCII码";
CM_ SG_ 2417749586 S2P_Cfg11_HW_Ver_Byte11_18 "CSC硬件版本号Byte11对应的ASCII码";
CM_ SG_ 2417749586 S2P_Cfg11_HW_Ver_Byte12_18 "CSC硬件版本号Byte12对应的ASCII码";
CM_ SG_ 2417749586 S2P_Cfg11_HW_Ver_Byte13_18 "CSC硬件版本号Byte13对应的ASCII码";
CM_ SG_ 2417749586 S2P_Cfg11_HW_Ver_Byte14_18 "CSC硬件版本号Byte14对应的ASCII码";
CM_ SG_ 2417749586 S2P_Cfg11_HW_Ver_Byte15_18 "CSC硬件版本号Byte15对应的ASCII码";
CM_ SG_ 2417749586 S2P_Cfg11_HW_Ver_Byte16_18 "CSC硬件版本号最高字节Byte16对应的ASCII码";
CM_ SG_ 2417749587 S2P_Cfg11_HW_Ver_Byte9_19 "CSC硬件版本号Byte9对应的ASCII码";
CM_ SG_ 2417749587 S2P_Cfg11_HW_Ver_Byte10_19 "CSC硬件版本号Byte10对应的ASCII码";
CM_ SG_ 2417749587 S2P_Cfg11_HW_Ver_Byte11_19 "CSC硬件版本号Byte11对应的ASCII码";
CM_ SG_ 2417749587 S2P_Cfg11_HW_Ver_Byte12_19 "CSC硬件版本号Byte12对应的ASCII码";
CM_ SG_ 2417749587 S2P_Cfg11_HW_Ver_Byte13_19 "CSC硬件版本号Byte13对应的ASCII码";
CM_ SG_ 2417749587 S2P_Cfg11_HW_Ver_Byte14_19 "CSC硬件版本号Byte14对应的ASCII码";
CM_ SG_ 2417749587 S2P_Cfg11_HW_Ver_Byte15_19 "CSC硬件版本号Byte15对应的ASCII码";
CM_ SG_ 2417749587 S2P_Cfg11_HW_Ver_Byte16_19 "CSC硬件版本号最高字节Byte16对应的ASCII码";
CM_ SG_ 2417749588 S2P_Cfg11_HW_Ver_Byte9_20 "CSC硬件版本号Byte9对应的ASCII码";
CM_ SG_ 2417749588 S2P_Cfg11_HW_Ver_Byte10_20 "CSC硬件版本号Byte10对应的ASCII码";
CM_ SG_ 2417749588 S2P_Cfg11_HW_Ver_Byte11_20 "CSC硬件版本号Byte11对应的ASCII码";
CM_ SG_ 2417749588 S2P_Cfg11_HW_Ver_Byte12_20 "CSC硬件版本号Byte12对应的ASCII码";
CM_ SG_ 2417749588 S2P_Cfg11_HW_Ver_Byte13_20 "CSC硬件版本号Byte13对应的ASCII码";
CM_ SG_ 2417749588 S2P_Cfg11_HW_Ver_Byte14_20 "CSC硬件版本号Byte14对应的ASCII码";
CM_ SG_ 2417749588 S2P_Cfg11_HW_Ver_Byte15_20 "CSC硬件版本号Byte15对应的ASCII码";
CM_ SG_ 2417749588 S2P_Cfg11_HW_Ver_Byte16_20 "CSC硬件版本号最高字节Byte16对应的ASCII码";
CM_ SG_ 2417749589 S2P_Cfg11_HW_Ver_Byte9_21 "CSC硬件版本号Byte9对应的ASCII码";
CM_ SG_ 2417749589 S2P_Cfg11_HW_Ver_Byte10_21 "CSC硬件版本号Byte10对应的ASCII码";
CM_ SG_ 2417749589 S2P_Cfg11_HW_Ver_Byte11_21 "CSC硬件版本号Byte11对应的ASCII码";
CM_ SG_ 2417749589 S2P_Cfg11_HW_Ver_Byte12_21 "CSC硬件版本号Byte12对应的ASCII码";
CM_ SG_ 2417749589 S2P_Cfg11_HW_Ver_Byte13_21 "CSC硬件版本号Byte13对应的ASCII码";
CM_ SG_ 2417749589 S2P_Cfg11_HW_Ver_Byte14_21 "CSC硬件版本号Byte14对应的ASCII码";
CM_ SG_ 2417749589 S2P_Cfg11_HW_Ver_Byte15_21 "CSC硬件版本号Byte15对应的ASCII码";
CM_ SG_ 2417749589 S2P_Cfg11_HW_Ver_Byte16_21 "CSC硬件版本号最高字节Byte16对应的ASCII码";
CM_ SG_ 2417749590 S2P_Cfg11_HW_Ver_Byte9_22 "CSC硬件版本号Byte9对应的ASCII码";
CM_ SG_ 2417749590 S2P_Cfg11_HW_Ver_Byte10_22 "CSC硬件版本号Byte10对应的ASCII码";
CM_ SG_ 2417749590 S2P_Cfg11_HW_Ver_Byte11_22 "CSC硬件版本号Byte11对应的ASCII码";
CM_ SG_ 2417749590 S2P_Cfg11_HW_Ver_Byte12_22 "CSC硬件版本号Byte12对应的ASCII码";
CM_ SG_ 2417749590 S2P_Cfg11_HW_Ver_Byte13_22 "CSC硬件版本号Byte13对应的ASCII码";
CM_ SG_ 2417749590 S2P_Cfg11_HW_Ver_Byte14_22 "CSC硬件版本号Byte14对应的ASCII码";
CM_ SG_ 2417749590 S2P_Cfg11_HW_Ver_Byte15_22 "CSC硬件版本号Byte15对应的ASCII码";
CM_ SG_ 2417749590 S2P_Cfg11_HW_Ver_Byte16_22 "CSC硬件版本号最高字节Byte16对应的ASCII码";
CM_ SG_ 2417749591 S2P_Cfg11_HW_Ver_Byte9_23 "CSC硬件版本号Byte9对应的ASCII码";
CM_ SG_ 2417749591 S2P_Cfg11_HW_Ver_Byte10_23 "CSC硬件版本号Byte10对应的ASCII码";
CM_ SG_ 2417749591 S2P_Cfg11_HW_Ver_Byte11_23 "CSC硬件版本号Byte11对应的ASCII码";
CM_ SG_ 2417749591 S2P_Cfg11_HW_Ver_Byte12_23 "CSC硬件版本号Byte12对应的ASCII码";
CM_ SG_ 2417749591 S2P_Cfg11_HW_Ver_Byte13_23 "CSC硬件版本号Byte13对应的ASCII码";
CM_ SG_ 2417749591 S2P_Cfg11_HW_Ver_Byte14_23 "CSC硬件版本号Byte14对应的ASCII码";
CM_ SG_ 2417749591 S2P_Cfg11_HW_Ver_Byte15_23 "CSC硬件版本号Byte15对应的ASCII码";
CM_ SG_ 2417749591 S2P_Cfg11_HW_Ver_Byte16_23 "CSC硬件版本号最高字节Byte16对应的ASCII码";
CM_ SG_ 2417749592 S2P_Cfg11_HW_Ver_Byte9_24 "CSC硬件版本号Byte9对应的ASCII码";
CM_ SG_ 2417749592 S2P_Cfg11_HW_Ver_Byte10_24 "CSC硬件版本号Byte10对应的ASCII码";
CM_ SG_ 2417749592 S2P_Cfg11_HW_Ver_Byte11_24 "CSC硬件版本号Byte11对应的ASCII码";
CM_ SG_ 2417749592 S2P_Cfg11_HW_Ver_Byte12_24 "CSC硬件版本号Byte12对应的ASCII码";
CM_ SG_ 2417749592 S2P_Cfg11_HW_Ver_Byte13_24 "CSC硬件版本号Byte13对应的ASCII码";
CM_ SG_ 2417749592 S2P_Cfg11_HW_Ver_Byte14_24 "CSC硬件版本号Byte14对应的ASCII码";
CM_ SG_ 2417749592 S2P_Cfg11_HW_Ver_Byte15_24 "CSC硬件版本号Byte15对应的ASCII码";
CM_ SG_ 2417749592 S2P_Cfg11_HW_Ver_Byte16_24 "CSC硬件版本号最高字节Byte16对应的ASCII码";
CM_ SG_ 2417749593 S2P_Cfg11_HW_Ver_Byte9_25 "CSC硬件版本号Byte9对应的ASCII码";
CM_ SG_ 2417749593 S2P_Cfg11_HW_Ver_Byte10_25 "CSC硬件版本号Byte10对应的ASCII码";
CM_ SG_ 2417749593 S2P_Cfg11_HW_Ver_Byte11_25 "CSC硬件版本号Byte11对应的ASCII码";
CM_ SG_ 2417749593 S2P_Cfg11_HW_Ver_Byte12_25 "CSC硬件版本号Byte12对应的ASCII码";
CM_ SG_ 2417749593 S2P_Cfg11_HW_Ver_Byte13_25 "CSC硬件版本号Byte13对应的ASCII码";
CM_ SG_ 2417749593 S2P_Cfg11_HW_Ver_Byte14_25 "CSC硬件版本号Byte14对应的ASCII码";
CM_ SG_ 2417749593 S2P_Cfg11_HW_Ver_Byte15_25 "CSC硬件版本号Byte15对应的ASCII码";
CM_ SG_ 2417749593 S2P_Cfg11_HW_Ver_Byte16_25 "CSC硬件版本号最高字节Byte16对应的ASCII码";
CM_ SG_ 2417749594 S2P_Cfg11_HW_Ver_Byte9_26 "CSC硬件版本号Byte9对应的ASCII码";
CM_ SG_ 2417749594 S2P_Cfg11_HW_Ver_Byte10_26 "CSC硬件版本号Byte10对应的ASCII码";
CM_ SG_ 2417749594 S2P_Cfg11_HW_Ver_Byte11_26 "CSC硬件版本号Byte11对应的ASCII码";
CM_ SG_ 2417749594 S2P_Cfg11_HW_Ver_Byte12_26 "CSC硬件版本号Byte12对应的ASCII码";
CM_ SG_ 2417749594 S2P_Cfg11_HW_Ver_Byte13_26 "CSC硬件版本号Byte13对应的ASCII码";
CM_ SG_ 2417749594 S2P_Cfg11_HW_Ver_Byte14_26 "CSC硬件版本号Byte14对应的ASCII码";
CM_ SG_ 2417749594 S2P_Cfg11_HW_Ver_Byte15_26 "CSC硬件版本号Byte15对应的ASCII码";
CM_ SG_ 2417749594 S2P_Cfg11_HW_Ver_Byte16_26 "CSC硬件版本号最高字节Byte16对应的ASCII码";
CM_ SG_ 2417749595 S2P_Cfg11_HW_Ver_Byte9_27 "CSC硬件版本号Byte9对应的ASCII码";
CM_ SG_ 2417749595 S2P_Cfg11_HW_Ver_Byte10_27 "CSC硬件版本号Byte10对应的ASCII码";
CM_ SG_ 2417749595 S2P_Cfg11_HW_Ver_Byte11_27 "CSC硬件版本号Byte11对应的ASCII码";
CM_ SG_ 2417749595 S2P_Cfg11_HW_Ver_Byte12_27 "CSC硬件版本号Byte12对应的ASCII码";
CM_ SG_ 2417749595 S2P_Cfg11_HW_Ver_Byte13_27 "CSC硬件版本号Byte13对应的ASCII码";
CM_ SG_ 2417749595 S2P_Cfg11_HW_Ver_Byte14_27 "CSC硬件版本号Byte14对应的ASCII码";
CM_ SG_ 2417749595 S2P_Cfg11_HW_Ver_Byte15_27 "CSC硬件版本号Byte15对应的ASCII码";
CM_ SG_ 2417749595 S2P_Cfg11_HW_Ver_Byte16_27 "CSC硬件版本号最高字节Byte16对应的ASCII码";
CM_ SG_ 2417749596 S2P_Cfg11_HW_Ver_Byte9_28 "CSC硬件版本号Byte9对应的ASCII码";
CM_ SG_ 2417749596 S2P_Cfg11_HW_Ver_Byte10_28 "CSC硬件版本号Byte10对应的ASCII码";
CM_ SG_ 2417749596 S2P_Cfg11_HW_Ver_Byte11_28 "CSC硬件版本号Byte11对应的ASCII码";
CM_ SG_ 2417749596 S2P_Cfg11_HW_Ver_Byte12_28 "CSC硬件版本号Byte12对应的ASCII码";
CM_ SG_ 2417749596 S2P_Cfg11_HW_Ver_Byte13_28 "CSC硬件版本号Byte13对应的ASCII码";
CM_ SG_ 2417749596 S2P_Cfg11_HW_Ver_Byte14_28 "CSC硬件版本号Byte14对应的ASCII码";
CM_ SG_ 2417749596 S2P_Cfg11_HW_Ver_Byte15_28 "CSC硬件版本号Byte15对应的ASCII码";
CM_ SG_ 2417749596 S2P_Cfg11_HW_Ver_Byte16_28 "CSC硬件版本号最高字节Byte16对应的ASCII码";
CM_ SG_ 2417749597 S2P_Cfg11_HW_Ver_Byte9_29 "CSC硬件版本号Byte9对应的ASCII码";
CM_ SG_ 2417749597 S2P_Cfg11_HW_Ver_Byte10_29 "CSC硬件版本号Byte10对应的ASCII码";
CM_ SG_ 2417749597 S2P_Cfg11_HW_Ver_Byte11_29 "CSC硬件版本号Byte11对应的ASCII码";
CM_ SG_ 2417749597 S2P_Cfg11_HW_Ver_Byte12_29 "CSC硬件版本号Byte12对应的ASCII码";
CM_ SG_ 2417749597 S2P_Cfg11_HW_Ver_Byte13_29 "CSC硬件版本号Byte13对应的ASCII码";
CM_ SG_ 2417749597 S2P_Cfg11_HW_Ver_Byte14_29 "CSC硬件版本号Byte14对应的ASCII码";
CM_ SG_ 2417749597 S2P_Cfg11_HW_Ver_Byte15_29 "CSC硬件版本号Byte15对应的ASCII码";
CM_ SG_ 2417749597 S2P_Cfg11_HW_Ver_Byte16_29 "CSC硬件版本号最高字节Byte16对应的ASCII码";
CM_ SG_ 2417749598 S2P_Cfg11_HW_Ver_Byte9_30 "CSC硬件版本号Byte9对应的ASCII码";
CM_ SG_ 2417749598 S2P_Cfg11_HW_Ver_Byte10_30 "CSC硬件版本号Byte10对应的ASCII码";
CM_ SG_ 2417749598 S2P_Cfg11_HW_Ver_Byte11_30 "CSC硬件版本号Byte11对应的ASCII码";
CM_ SG_ 2417749598 S2P_Cfg11_HW_Ver_Byte12_30 "CSC硬件版本号Byte12对应的ASCII码";
CM_ SG_ 2417749598 S2P_Cfg11_HW_Ver_Byte13_30 "CSC硬件版本号Byte13对应的ASCII码";
CM_ SG_ 2417749598 S2P_Cfg11_HW_Ver_Byte14_30 "CSC硬件版本号Byte14对应的ASCII码";
CM_ SG_ 2417749598 S2P_Cfg11_HW_Ver_Byte15_30 "CSC硬件版本号Byte15对应的ASCII码";
CM_ SG_ 2417749598 S2P_Cfg11_HW_Ver_Byte16_30 "CSC硬件版本号最高字节Byte16对应的ASCII码";
CM_ SG_ 2417749599 S2P_Cfg11_HW_Ver_Byte9_31 "CSC硬件版本号Byte9对应的ASCII码";
CM_ SG_ 2417749599 S2P_Cfg11_HW_Ver_Byte10_31 "CSC硬件版本号Byte10对应的ASCII码";
CM_ SG_ 2417749599 S2P_Cfg11_HW_Ver_Byte11_31 "CSC硬件版本号Byte11对应的ASCII码";
CM_ SG_ 2417749599 S2P_Cfg11_HW_Ver_Byte12_31 "CSC硬件版本号Byte12对应的ASCII码";
CM_ SG_ 2417749599 S2P_Cfg11_HW_Ver_Byte13_31 "CSC硬件版本号Byte13对应的ASCII码";
CM_ SG_ 2417749599 S2P_Cfg11_HW_Ver_Byte14_31 "CSC硬件版本号Byte14对应的ASCII码";
CM_ SG_ 2417749599 S2P_Cfg11_HW_Ver_Byte15_31 "CSC硬件版本号Byte15对应的ASCII码";
CM_ SG_ 2417749599 S2P_Cfg11_HW_Ver_Byte16_31 "CSC硬件版本号最高字节Byte16对应的ASCII码";
CM_ SG_ 2417749600 S2P_Cfg11_HW_Ver_Byte9_32 "CSC硬件版本号Byte9对应的ASCII码";
CM_ SG_ 2417749600 S2P_Cfg11_HW_Ver_Byte10_32 "CSC硬件版本号Byte10对应的ASCII码";
CM_ SG_ 2417749600 S2P_Cfg11_HW_Ver_Byte11_32 "CSC硬件版本号Byte11对应的ASCII码";
CM_ SG_ 2417749600 S2P_Cfg11_HW_Ver_Byte12_32 "CSC硬件版本号Byte12对应的ASCII码";
CM_ SG_ 2417749600 S2P_Cfg11_HW_Ver_Byte13_32 "CSC硬件版本号Byte13对应的ASCII码";
CM_ SG_ 2417749600 S2P_Cfg11_HW_Ver_Byte14_32 "CSC硬件版本号Byte14对应的ASCII码";
CM_ SG_ 2417749600 S2P_Cfg11_HW_Ver_Byte15_32 "CSC硬件版本号Byte15对应的ASCII码";
CM_ SG_ 2417749600 S2P_Cfg11_HW_Ver_Byte16_32 "CSC硬件版本号最高字节Byte16对应的ASCII码";
CM_ SG_ 2417749601 S2P_Cfg11_HW_Ver_Byte9_33 "CSC硬件版本号Byte9对应的ASCII码";
CM_ SG_ 2417749601 S2P_Cfg11_HW_Ver_Byte10_33 "CSC硬件版本号Byte10对应的ASCII码";
CM_ SG_ 2417749601 S2P_Cfg11_HW_Ver_Byte11_33 "CSC硬件版本号Byte11对应的ASCII码";
CM_ SG_ 2417749601 S2P_Cfg11_HW_Ver_Byte12_33 "CSC硬件版本号Byte12对应的ASCII码";
CM_ SG_ 2417749601 S2P_Cfg11_HW_Ver_Byte13_33 "CSC硬件版本号Byte13对应的ASCII码";
CM_ SG_ 2417749601 S2P_Cfg11_HW_Ver_Byte14_33 "CSC硬件版本号Byte14对应的ASCII码";
CM_ SG_ 2417749601 S2P_Cfg11_HW_Ver_Byte15_33 "CSC硬件版本号Byte15对应的ASCII码";
CM_ SG_ 2417749601 S2P_Cfg11_HW_Ver_Byte16_33 "CSC硬件版本号最高字节Byte16对应的ASCII码";
CM_ SG_ 2417749602 S2P_Cfg11_HW_Ver_Byte9_34 "CSC硬件版本号Byte9对应的ASCII码";
CM_ SG_ 2417749602 S2P_Cfg11_HW_Ver_Byte10_34 "CSC硬件版本号Byte10对应的ASCII码";
CM_ SG_ 2417749602 S2P_Cfg11_HW_Ver_Byte11_34 "CSC硬件版本号Byte11对应的ASCII码";
CM_ SG_ 2417749602 S2P_Cfg11_HW_Ver_Byte12_34 "CSC硬件版本号Byte12对应的ASCII码";
CM_ SG_ 2417749602 S2P_Cfg11_HW_Ver_Byte13_34 "CSC硬件版本号Byte13对应的ASCII码";
CM_ SG_ 2417749602 S2P_Cfg11_HW_Ver_Byte14_34 "CSC硬件版本号Byte14对应的ASCII码";
CM_ SG_ 2417749602 S2P_Cfg11_HW_Ver_Byte15_34 "CSC硬件版本号Byte15对应的ASCII码";
CM_ SG_ 2417749602 S2P_Cfg11_HW_Ver_Byte16_34 "CSC硬件版本号最高字节Byte16对应的ASCII码";
CM_ SG_ 2417749603 S2P_Cfg11_HW_Ver_Byte9_35 "CSC硬件版本号Byte9对应的ASCII码";
CM_ SG_ 2417749603 S2P_Cfg11_HW_Ver_Byte10_35 "CSC硬件版本号Byte10对应的ASCII码";
CM_ SG_ 2417749603 S2P_Cfg11_HW_Ver_Byte11_35 "CSC硬件版本号Byte11对应的ASCII码";
CM_ SG_ 2417749603 S2P_Cfg11_HW_Ver_Byte12_35 "CSC硬件版本号Byte12对应的ASCII码";
CM_ SG_ 2417749603 S2P_Cfg11_HW_Ver_Byte13_35 "CSC硬件版本号Byte13对应的ASCII码";
CM_ SG_ 2417749603 S2P_Cfg11_HW_Ver_Byte14_35 "CSC硬件版本号Byte14对应的ASCII码";
CM_ SG_ 2417749603 S2P_Cfg11_HW_Ver_Byte15_35 "CSC硬件版本号Byte15对应的ASCII码";
CM_ SG_ 2417749603 S2P_Cfg11_HW_Ver_Byte16_35 "CSC硬件版本号最高字节Byte16对应的ASCII码";
CM_ SG_ 2417749604 S2P_Cfg11_HW_Ver_Byte9_36 "CSC硬件版本号Byte9对应的ASCII码";
CM_ SG_ 2417749604 S2P_Cfg11_HW_Ver_Byte10_36 "CSC硬件版本号Byte10对应的ASCII码";
CM_ SG_ 2417749604 S2P_Cfg11_HW_Ver_Byte11_36 "CSC硬件版本号Byte11对应的ASCII码";
CM_ SG_ 2417749604 S2P_Cfg11_HW_Ver_Byte12_36 "CSC硬件版本号Byte12对应的ASCII码";
CM_ SG_ 2417749604 S2P_Cfg11_HW_Ver_Byte13_36 "CSC硬件版本号Byte13对应的ASCII码";
CM_ SG_ 2417749604 S2P_Cfg11_HW_Ver_Byte14_36 "CSC硬件版本号Byte14对应的ASCII码";
CM_ SG_ 2417749604 S2P_Cfg11_HW_Ver_Byte15_36 "CSC硬件版本号Byte15对应的ASCII码";
CM_ SG_ 2417749604 S2P_Cfg11_HW_Ver_Byte16_36 "CSC硬件版本号最高字节Byte16对应的ASCII码";
CM_ SG_ 2417749605 S2P_Cfg11_HW_Ver_Byte9_37 "CSC硬件版本号Byte9对应的ASCII码";
CM_ SG_ 2417749605 S2P_Cfg11_HW_Ver_Byte10_37 "CSC硬件版本号Byte10对应的ASCII码";
CM_ SG_ 2417749605 S2P_Cfg11_HW_Ver_Byte11_37 "CSC硬件版本号Byte11对应的ASCII码";
CM_ SG_ 2417749605 S2P_Cfg11_HW_Ver_Byte12_37 "CSC硬件版本号Byte12对应的ASCII码";
CM_ SG_ 2417749605 S2P_Cfg11_HW_Ver_Byte13_37 "CSC硬件版本号Byte13对应的ASCII码";
CM_ SG_ 2417749605 S2P_Cfg11_HW_Ver_Byte14_37 "CSC硬件版本号Byte14对应的ASCII码";
CM_ SG_ 2417749605 S2P_Cfg11_HW_Ver_Byte15_37 "CSC硬件版本号Byte15对应的ASCII码";
CM_ SG_ 2417749605 S2P_Cfg11_HW_Ver_Byte16_37 "CSC硬件版本号最高字节Byte16对应的ASCII码";
CM_ SG_ 2417749606 S2P_Cfg11_HW_Ver_Byte9_38 "CSC硬件版本号Byte9对应的ASCII码";
CM_ SG_ 2417749606 S2P_Cfg11_HW_Ver_Byte10_38 "CSC硬件版本号Byte10对应的ASCII码";
CM_ SG_ 2417749606 S2P_Cfg11_HW_Ver_Byte11_38 "CSC硬件版本号Byte11对应的ASCII码";
CM_ SG_ 2417749606 S2P_Cfg11_HW_Ver_Byte12_38 "CSC硬件版本号Byte12对应的ASCII码";
CM_ SG_ 2417749606 S2P_Cfg11_HW_Ver_Byte13_38 "CSC硬件版本号Byte13对应的ASCII码";
CM_ SG_ 2417749606 S2P_Cfg11_HW_Ver_Byte14_38 "CSC硬件版本号Byte14对应的ASCII码";
CM_ SG_ 2417749606 S2P_Cfg11_HW_Ver_Byte15_38 "CSC硬件版本号Byte15对应的ASCII码";
CM_ SG_ 2417749606 S2P_Cfg11_HW_Ver_Byte16_38 "CSC硬件版本号最高字节Byte16对应的ASCII码";
CM_ SG_ 2417749607 S2P_Cfg11_HW_Ver_Byte9_39 "CSC硬件版本号Byte9对应的ASCII码";
CM_ SG_ 2417749607 S2P_Cfg11_HW_Ver_Byte10_39 "CSC硬件版本号Byte10对应的ASCII码";
CM_ SG_ 2417749607 S2P_Cfg11_HW_Ver_Byte11_39 "CSC硬件版本号Byte11对应的ASCII码";
CM_ SG_ 2417749607 S2P_Cfg11_HW_Ver_Byte12_39 "CSC硬件版本号Byte12对应的ASCII码";
CM_ SG_ 2417749607 S2P_Cfg11_HW_Ver_Byte13_39 "CSC硬件版本号Byte13对应的ASCII码";
CM_ SG_ 2417749607 S2P_Cfg11_HW_Ver_Byte14_39 "CSC硬件版本号Byte14对应的ASCII码";
CM_ SG_ 2417749607 S2P_Cfg11_HW_Ver_Byte15_39 "CSC硬件版本号Byte15对应的ASCII码";
CM_ SG_ 2417749607 S2P_Cfg11_HW_Ver_Byte16_39 "CSC硬件版本号最高字节Byte16对应的ASCII码";
CM_ SG_ 2417749608 S2P_Cfg11_HW_Ver_Byte9_40 "CSC硬件版本号Byte9对应的ASCII码";
CM_ SG_ 2417749608 S2P_Cfg11_HW_Ver_Byte10_40 "CSC硬件版本号Byte10对应的ASCII码";
CM_ SG_ 2417749608 S2P_Cfg11_HW_Ver_Byte11_40 "CSC硬件版本号Byte11对应的ASCII码";
CM_ SG_ 2417749608 S2P_Cfg11_HW_Ver_Byte12_40 "CSC硬件版本号Byte12对应的ASCII码";
CM_ SG_ 2417749608 S2P_Cfg11_HW_Ver_Byte13_40 "CSC硬件版本号Byte13对应的ASCII码";
CM_ SG_ 2417749608 S2P_Cfg11_HW_Ver_Byte14_40 "CSC硬件版本号Byte14对应的ASCII码";
CM_ SG_ 2417749608 S2P_Cfg11_HW_Ver_Byte15_40 "CSC硬件版本号Byte15对应的ASCII码";
CM_ SG_ 2417749608 S2P_Cfg11_HW_Ver_Byte16_40 "CSC硬件版本号最高字节Byte16对应的ASCII码";
CM_ SG_ 2417749609 S2P_Cfg11_HW_Ver_Byte9_41 "CSC硬件版本号Byte9对应的ASCII码";
CM_ SG_ 2417749609 S2P_Cfg11_HW_Ver_Byte10_41 "CSC硬件版本号Byte10对应的ASCII码";
CM_ SG_ 2417749609 S2P_Cfg11_HW_Ver_Byte11_41 "CSC硬件版本号Byte11对应的ASCII码";
CM_ SG_ 2417749609 S2P_Cfg11_HW_Ver_Byte12_41 "CSC硬件版本号Byte12对应的ASCII码";
CM_ SG_ 2417749609 S2P_Cfg11_HW_Ver_Byte13_41 "CSC硬件版本号Byte13对应的ASCII码";
CM_ SG_ 2417749609 S2P_Cfg11_HW_Ver_Byte14_41 "CSC硬件版本号Byte14对应的ASCII码";
CM_ SG_ 2417749609 S2P_Cfg11_HW_Ver_Byte15_41 "CSC硬件版本号Byte15对应的ASCII码";
CM_ SG_ 2417749609 S2P_Cfg11_HW_Ver_Byte16_41 "CSC硬件版本号最高字节Byte16对应的ASCII码";
CM_ SG_ 2417749610 S2P_Cfg11_HW_Ver_Byte9_42 "CSC硬件版本号Byte9对应的ASCII码";
CM_ SG_ 2417749610 S2P_Cfg11_HW_Ver_Byte10_42 "CSC硬件版本号Byte10对应的ASCII码";
CM_ SG_ 2417749610 S2P_Cfg11_HW_Ver_Byte11_42 "CSC硬件版本号Byte11对应的ASCII码";
CM_ SG_ 2417749610 S2P_Cfg11_HW_Ver_Byte12_42 "CSC硬件版本号Byte12对应的ASCII码";
CM_ SG_ 2417749610 S2P_Cfg11_HW_Ver_Byte13_42 "CSC硬件版本号Byte13对应的ASCII码";
CM_ SG_ 2417749610 S2P_Cfg11_HW_Ver_Byte14_42 "CSC硬件版本号Byte14对应的ASCII码";
CM_ SG_ 2417749610 S2P_Cfg11_HW_Ver_Byte15_42 "CSC硬件版本号Byte15对应的ASCII码";
CM_ SG_ 2417749610 S2P_Cfg11_HW_Ver_Byte16_42 "CSC硬件版本号最高字节Byte16对应的ASCII码";
CM_ SG_ 2417749611 S2P_Cfg11_HW_Ver_Byte9_43 "CSC硬件版本号Byte9对应的ASCII码";
CM_ SG_ 2417749611 S2P_Cfg11_HW_Ver_Byte10_43 "CSC硬件版本号Byte10对应的ASCII码";
CM_ SG_ 2417749611 S2P_Cfg11_HW_Ver_Byte11_43 "CSC硬件版本号Byte11对应的ASCII码";
CM_ SG_ 2417749611 S2P_Cfg11_HW_Ver_Byte12_43 "CSC硬件版本号Byte12对应的ASCII码";
CM_ SG_ 2417749611 S2P_Cfg11_HW_Ver_Byte13_43 "CSC硬件版本号Byte13对应的ASCII码";
CM_ SG_ 2417749611 S2P_Cfg11_HW_Ver_Byte14_43 "CSC硬件版本号Byte14对应的ASCII码";
CM_ SG_ 2417749611 S2P_Cfg11_HW_Ver_Byte15_43 "CSC硬件版本号Byte15对应的ASCII码";
CM_ SG_ 2417749611 S2P_Cfg11_HW_Ver_Byte16_43 "CSC硬件版本号最高字节Byte16对应的ASCII码";
CM_ SG_ 2417749612 S2P_Cfg11_HW_Ver_Byte9_44 "CSC硬件版本号Byte9对应的ASCII码";
CM_ SG_ 2417749612 S2P_Cfg11_HW_Ver_Byte10_44 "CSC硬件版本号Byte10对应的ASCII码";
CM_ SG_ 2417749612 S2P_Cfg11_HW_Ver_Byte11_44 "CSC硬件版本号Byte11对应的ASCII码";
CM_ SG_ 2417749612 S2P_Cfg11_HW_Ver_Byte12_44 "CSC硬件版本号Byte12对应的ASCII码";
CM_ SG_ 2417749612 S2P_Cfg11_HW_Ver_Byte13_44 "CSC硬件版本号Byte13对应的ASCII码";
CM_ SG_ 2417749612 S2P_Cfg11_HW_Ver_Byte14_44 "CSC硬件版本号Byte14对应的ASCII码";
CM_ SG_ 2417749612 S2P_Cfg11_HW_Ver_Byte15_44 "CSC硬件版本号Byte15对应的ASCII码";
CM_ SG_ 2417749612 S2P_Cfg11_HW_Ver_Byte16_44 "CSC硬件版本号最高字节Byte16对应的ASCII码";
CM_ SG_ 2417749613 S2P_Cfg11_HW_Ver_Byte9_45 "CSC硬件版本号Byte9对应的ASCII码";
CM_ SG_ 2417749613 S2P_Cfg11_HW_Ver_Byte10_45 "CSC硬件版本号Byte10对应的ASCII码";
CM_ SG_ 2417749613 S2P_Cfg11_HW_Ver_Byte11_45 "CSC硬件版本号Byte11对应的ASCII码";
CM_ SG_ 2417749613 S2P_Cfg11_HW_Ver_Byte12_45 "CSC硬件版本号Byte12对应的ASCII码";
CM_ SG_ 2417749613 S2P_Cfg11_HW_Ver_Byte13_45 "CSC硬件版本号Byte13对应的ASCII码";
CM_ SG_ 2417749613 S2P_Cfg11_HW_Ver_Byte14_45 "CSC硬件版本号Byte14对应的ASCII码";
CM_ SG_ 2417749613 S2P_Cfg11_HW_Ver_Byte15_45 "CSC硬件版本号Byte15对应的ASCII码";
CM_ SG_ 2417749613 S2P_Cfg11_HW_Ver_Byte16_45 "CSC硬件版本号最高字节Byte16对应的ASCII码";
CM_ SG_ 2417749614 S2P_Cfg11_HW_Ver_Byte9_46 "CSC硬件版本号Byte9对应的ASCII码";
CM_ SG_ 2417749614 S2P_Cfg11_HW_Ver_Byte10_46 "CSC硬件版本号Byte10对应的ASCII码";
CM_ SG_ 2417749614 S2P_Cfg11_HW_Ver_Byte11_46 "CSC硬件版本号Byte11对应的ASCII码";
CM_ SG_ 2417749614 S2P_Cfg11_HW_Ver_Byte12_46 "CSC硬件版本号Byte12对应的ASCII码";
CM_ SG_ 2417749614 S2P_Cfg11_HW_Ver_Byte13_46 "CSC硬件版本号Byte13对应的ASCII码";
CM_ SG_ 2417749614 S2P_Cfg11_HW_Ver_Byte14_46 "CSC硬件版本号Byte14对应的ASCII码";
CM_ SG_ 2417749614 S2P_Cfg11_HW_Ver_Byte15_46 "CSC硬件版本号Byte15对应的ASCII码";
CM_ SG_ 2417749614 S2P_Cfg11_HW_Ver_Byte16_46 "CSC硬件版本号最高字节Byte16对应的ASCII码";
CM_ SG_ 2417749615 S2P_Cfg11_HW_Ver_Byte9_47 "CSC硬件版本号Byte9对应的ASCII码";
CM_ SG_ 2417749615 S2P_Cfg11_HW_Ver_Byte10_47 "CSC硬件版本号Byte10对应的ASCII码";
CM_ SG_ 2417749615 S2P_Cfg11_HW_Ver_Byte11_47 "CSC硬件版本号Byte11对应的ASCII码";
CM_ SG_ 2417749615 S2P_Cfg11_HW_Ver_Byte12_47 "CSC硬件版本号Byte12对应的ASCII码";
CM_ SG_ 2417749615 S2P_Cfg11_HW_Ver_Byte13_47 "CSC硬件版本号Byte13对应的ASCII码";
CM_ SG_ 2417749615 S2P_Cfg11_HW_Ver_Byte14_47 "CSC硬件版本号Byte14对应的ASCII码";
CM_ SG_ 2417749615 S2P_Cfg11_HW_Ver_Byte15_47 "CSC硬件版本号Byte15对应的ASCII码";
CM_ SG_ 2417749615 S2P_Cfg11_HW_Ver_Byte16_47 "CSC硬件版本号最高字节Byte16对应的ASCII码";
CM_ SG_ 2417749616 S2P_Cfg11_HW_Ver_Byte9_48 "CSC硬件版本号Byte9对应的ASCII码";
CM_ SG_ 2417749616 S2P_Cfg11_HW_Ver_Byte10_48 "CSC硬件版本号Byte10对应的ASCII码";
CM_ SG_ 2417749616 S2P_Cfg11_HW_Ver_Byte11_48 "CSC硬件版本号Byte11对应的ASCII码";
CM_ SG_ 2417749616 S2P_Cfg11_HW_Ver_Byte12_48 "CSC硬件版本号Byte12对应的ASCII码";
CM_ SG_ 2417749616 S2P_Cfg11_HW_Ver_Byte13_48 "CSC硬件版本号Byte13对应的ASCII码";
CM_ SG_ 2417749616 S2P_Cfg11_HW_Ver_Byte14_48 "CSC硬件版本号Byte14对应的ASCII码";
CM_ SG_ 2417749616 S2P_Cfg11_HW_Ver_Byte15_48 "CSC硬件版本号Byte15对应的ASCII码";
CM_ SG_ 2417749616 S2P_Cfg11_HW_Ver_Byte16_48 "CSC硬件版本号最高字节Byte16对应的ASCII码";
CM_ SG_ 2417749617 S2P_Cfg11_HW_Ver_Byte9_49 "CSC硬件版本号Byte9对应的ASCII码";
CM_ SG_ 2417749617 S2P_Cfg11_HW_Ver_Byte10_49 "CSC硬件版本号Byte10对应的ASCII码";
CM_ SG_ 2417749617 S2P_Cfg11_HW_Ver_Byte11_49 "CSC硬件版本号Byte11对应的ASCII码";
CM_ SG_ 2417749617 S2P_Cfg11_HW_Ver_Byte12_49 "CSC硬件版本号Byte12对应的ASCII码";
CM_ SG_ 2417749617 S2P_Cfg11_HW_Ver_Byte13_49 "CSC硬件版本号Byte13对应的ASCII码";
CM_ SG_ 2417749617 S2P_Cfg11_HW_Ver_Byte14_49 "CSC硬件版本号Byte14对应的ASCII码";
CM_ SG_ 2417749617 S2P_Cfg11_HW_Ver_Byte15_49 "CSC硬件版本号Byte15对应的ASCII码";
CM_ SG_ 2417749617 S2P_Cfg11_HW_Ver_Byte16_49 "CSC硬件版本号最高字节Byte16对应的ASCII码";
CM_ SG_ 2417749618 S2P_Cfg11_HW_Ver_Byte9_50 "CSC硬件版本号Byte9对应的ASCII码";
CM_ SG_ 2417749618 S2P_Cfg11_HW_Ver_Byte10_50 "CSC硬件版本号Byte10对应的ASCII码";
CM_ SG_ 2417749618 S2P_Cfg11_HW_Ver_Byte11_50 "CSC硬件版本号Byte11对应的ASCII码";
CM_ SG_ 2417749618 S2P_Cfg11_HW_Ver_Byte12_50 "CSC硬件版本号Byte12对应的ASCII码";
CM_ SG_ 2417749618 S2P_Cfg11_HW_Ver_Byte13_50 "CSC硬件版本号Byte13对应的ASCII码";
CM_ SG_ 2417749618 S2P_Cfg11_HW_Ver_Byte14_50 "CSC硬件版本号Byte14对应的ASCII码";
CM_ SG_ 2417749618 S2P_Cfg11_HW_Ver_Byte15_50 "CSC硬件版本号Byte15对应的ASCII码";
CM_ SG_ 2417749618 S2P_Cfg11_HW_Ver_Byte16_50 "CSC硬件版本号最高字节Byte16对应的ASCII码";
CM_ SG_ 2417749619 S2P_Cfg11_HW_Ver_Byte9_51 "CSC硬件版本号Byte9对应的ASCII码";
CM_ SG_ 2417749619 S2P_Cfg11_HW_Ver_Byte10_51 "CSC硬件版本号Byte10对应的ASCII码";
CM_ SG_ 2417749619 S2P_Cfg11_HW_Ver_Byte11_51 "CSC硬件版本号Byte11对应的ASCII码";
CM_ SG_ 2417749619 S2P_Cfg11_HW_Ver_Byte12_51 "CSC硬件版本号Byte12对应的ASCII码";
CM_ SG_ 2417749619 S2P_Cfg11_HW_Ver_Byte13_51 "CSC硬件版本号Byte13对应的ASCII码";
CM_ SG_ 2417749619 S2P_Cfg11_HW_Ver_Byte14_51 "CSC硬件版本号Byte14对应的ASCII码";
CM_ SG_ 2417749619 S2P_Cfg11_HW_Ver_Byte15_51 "CSC硬件版本号Byte15对应的ASCII码";
CM_ SG_ 2417749619 S2P_Cfg11_HW_Ver_Byte16_51 "CSC硬件版本号最高字节Byte16对应的ASCII码";
CM_ SG_ 2417749620 S2P_Cfg11_HW_Ver_Byte9_52 "CSC硬件版本号Byte9对应的ASCII码";
CM_ SG_ 2417749620 S2P_Cfg11_HW_Ver_Byte10_52 "CSC硬件版本号Byte10对应的ASCII码";
CM_ SG_ 2417749620 S2P_Cfg11_HW_Ver_Byte11_52 "CSC硬件版本号Byte11对应的ASCII码";
CM_ SG_ 2417749620 S2P_Cfg11_HW_Ver_Byte12_52 "CSC硬件版本号Byte12对应的ASCII码";
CM_ SG_ 2417749620 S2P_Cfg11_HW_Ver_Byte13_52 "CSC硬件版本号Byte13对应的ASCII码";
CM_ SG_ 2417749620 S2P_Cfg11_HW_Ver_Byte14_52 "CSC硬件版本号Byte14对应的ASCII码";
CM_ SG_ 2417749620 S2P_Cfg11_HW_Ver_Byte15_52 "CSC硬件版本号Byte15对应的ASCII码";
CM_ SG_ 2417749620 S2P_Cfg11_HW_Ver_Byte16_52 "CSC硬件版本号最高字节Byte16对应的ASCII码";
CM_ SG_ 2417749621 S2P_Cfg11_HW_Ver_Byte9_53 "CSC硬件版本号Byte9对应的ASCII码";
CM_ SG_ 2417749621 S2P_Cfg11_HW_Ver_Byte10_53 "CSC硬件版本号Byte10对应的ASCII码";
CM_ SG_ 2417749621 S2P_Cfg11_HW_Ver_Byte11_53 "CSC硬件版本号Byte11对应的ASCII码";
CM_ SG_ 2417749621 S2P_Cfg11_HW_Ver_Byte12_53 "CSC硬件版本号Byte12对应的ASCII码";
CM_ SG_ 2417749621 S2P_Cfg11_HW_Ver_Byte13_53 "CSC硬件版本号Byte13对应的ASCII码";
CM_ SG_ 2417749621 S2P_Cfg11_HW_Ver_Byte14_53 "CSC硬件版本号Byte14对应的ASCII码";
CM_ SG_ 2417749621 S2P_Cfg11_HW_Ver_Byte15_53 "CSC硬件版本号Byte15对应的ASCII码";
CM_ SG_ 2417749621 S2P_Cfg11_HW_Ver_Byte16_53 "CSC硬件版本号最高字节Byte16对应的ASCII码";
CM_ SG_ 2417749622 S2P_Cfg11_HW_Ver_Byte9_54 "CSC硬件版本号Byte9对应的ASCII码";
CM_ SG_ 2417749622 S2P_Cfg11_HW_Ver_Byte10_54 "CSC硬件版本号Byte10对应的ASCII码";
CM_ SG_ 2417749622 S2P_Cfg11_HW_Ver_Byte11_54 "CSC硬件版本号Byte11对应的ASCII码";
CM_ SG_ 2417749622 S2P_Cfg11_HW_Ver_Byte12_54 "CSC硬件版本号Byte12对应的ASCII码";
CM_ SG_ 2417749622 S2P_Cfg11_HW_Ver_Byte13_54 "CSC硬件版本号Byte13对应的ASCII码";
CM_ SG_ 2417749622 S2P_Cfg11_HW_Ver_Byte14_54 "CSC硬件版本号Byte14对应的ASCII码";
CM_ SG_ 2417749622 S2P_Cfg11_HW_Ver_Byte15_54 "CSC硬件版本号Byte15对应的ASCII码";
CM_ SG_ 2417749622 S2P_Cfg11_HW_Ver_Byte16_54 "CSC硬件版本号最高字节Byte16对应的ASCII码";
CM_ SG_ 2417749623 S2P_Cfg11_HW_Ver_Byte9_55 "CSC硬件版本号Byte9对应的ASCII码";
CM_ SG_ 2417749623 S2P_Cfg11_HW_Ver_Byte10_55 "CSC硬件版本号Byte10对应的ASCII码";
CM_ SG_ 2417749623 S2P_Cfg11_HW_Ver_Byte11_55 "CSC硬件版本号Byte11对应的ASCII码";
CM_ SG_ 2417749623 S2P_Cfg11_HW_Ver_Byte12_55 "CSC硬件版本号Byte12对应的ASCII码";
CM_ SG_ 2417749623 S2P_Cfg11_HW_Ver_Byte13_55 "CSC硬件版本号Byte13对应的ASCII码";
CM_ SG_ 2417749623 S2P_Cfg11_HW_Ver_Byte14_55 "CSC硬件版本号Byte14对应的ASCII码";
CM_ SG_ 2417749623 S2P_Cfg11_HW_Ver_Byte15_55 "CSC硬件版本号Byte15对应的ASCII码";
CM_ SG_ 2417749623 S2P_Cfg11_HW_Ver_Byte16_55 "CSC硬件版本号最高字节Byte16对应的ASCII码";
CM_ SG_ 2417749624 S2P_Cfg11_HW_Ver_Byte9_56 "CSC硬件版本号Byte9对应的ASCII码";
CM_ SG_ 2417749624 S2P_Cfg11_HW_Ver_Byte10_56 "CSC硬件版本号Byte10对应的ASCII码";
CM_ SG_ 2417749624 S2P_Cfg11_HW_Ver_Byte11_56 "CSC硬件版本号Byte11对应的ASCII码";
CM_ SG_ 2417749624 S2P_Cfg11_HW_Ver_Byte12_56 "CSC硬件版本号Byte12对应的ASCII码";
CM_ SG_ 2417749624 S2P_Cfg11_HW_Ver_Byte13_56 "CSC硬件版本号Byte13对应的ASCII码";
CM_ SG_ 2417749624 S2P_Cfg11_HW_Ver_Byte14_56 "CSC硬件版本号Byte14对应的ASCII码";
CM_ SG_ 2417749624 S2P_Cfg11_HW_Ver_Byte15_56 "CSC硬件版本号Byte15对应的ASCII码";
CM_ SG_ 2417749624 S2P_Cfg11_HW_Ver_Byte16_56 "CSC硬件版本号最高字节Byte16对应的ASCII码";
CM_ SG_ 2417749625 S2P_Cfg11_HW_Ver_Byte9_57 "CSC硬件版本号Byte9对应的ASCII码";
CM_ SG_ 2417749625 S2P_Cfg11_HW_Ver_Byte10_57 "CSC硬件版本号Byte10对应的ASCII码";
CM_ SG_ 2417749625 S2P_Cfg11_HW_Ver_Byte11_57 "CSC硬件版本号Byte11对应的ASCII码";
CM_ SG_ 2417749625 S2P_Cfg11_HW_Ver_Byte12_57 "CSC硬件版本号Byte12对应的ASCII码";
CM_ SG_ 2417749625 S2P_Cfg11_HW_Ver_Byte13_57 "CSC硬件版本号Byte13对应的ASCII码";
CM_ SG_ 2417749625 S2P_Cfg11_HW_Ver_Byte14_57 "CSC硬件版本号Byte14对应的ASCII码";
CM_ SG_ 2417749625 S2P_Cfg11_HW_Ver_Byte15_57 "CSC硬件版本号Byte15对应的ASCII码";
CM_ SG_ 2417749625 S2P_Cfg11_HW_Ver_Byte16_57 "CSC硬件版本号最高字节Byte16对应的ASCII码";
CM_ SG_ 2417749626 S2P_Cfg11_HW_Ver_Byte9_58 "CSC硬件版本号Byte9对应的ASCII码";
CM_ SG_ 2417749626 S2P_Cfg11_HW_Ver_Byte10_58 "CSC硬件版本号Byte10对应的ASCII码";
CM_ SG_ 2417749626 S2P_Cfg11_HW_Ver_Byte11_58 "CSC硬件版本号Byte11对应的ASCII码";
CM_ SG_ 2417749626 S2P_Cfg11_HW_Ver_Byte12_58 "CSC硬件版本号Byte12对应的ASCII码";
CM_ SG_ 2417749626 S2P_Cfg11_HW_Ver_Byte13_58 "CSC硬件版本号Byte13对应的ASCII码";
CM_ SG_ 2417749626 S2P_Cfg11_HW_Ver_Byte14_58 "CSC硬件版本号Byte14对应的ASCII码";
CM_ SG_ 2417749626 S2P_Cfg11_HW_Ver_Byte15_58 "CSC硬件版本号Byte15对应的ASCII码";
CM_ SG_ 2417749626 S2P_Cfg11_HW_Ver_Byte16_58 "CSC硬件版本号最高字节Byte16对应的ASCII码";
CM_ SG_ 2417749627 S2P_Cfg11_HW_Ver_Byte9_59 "CSC硬件版本号Byte9对应的ASCII码";
CM_ SG_ 2417749627 S2P_Cfg11_HW_Ver_Byte10_59 "CSC硬件版本号Byte10对应的ASCII码";
CM_ SG_ 2417749627 S2P_Cfg11_HW_Ver_Byte11_59 "CSC硬件版本号Byte11对应的ASCII码";
CM_ SG_ 2417749627 S2P_Cfg11_HW_Ver_Byte12_59 "CSC硬件版本号Byte12对应的ASCII码";
CM_ SG_ 2417749627 S2P_Cfg11_HW_Ver_Byte13_59 "CSC硬件版本号Byte13对应的ASCII码";
CM_ SG_ 2417749627 S2P_Cfg11_HW_Ver_Byte14_59 "CSC硬件版本号Byte14对应的ASCII码";
CM_ SG_ 2417749627 S2P_Cfg11_HW_Ver_Byte15_59 "CSC硬件版本号Byte15对应的ASCII码";
CM_ SG_ 2417749627 S2P_Cfg11_HW_Ver_Byte16_59 "CSC硬件版本号最高字节Byte16对应的ASCII码";
CM_ SG_ 2417749628 S2P_Cfg11_HW_Ver_Byte9_60 "CSC硬件版本号Byte9对应的ASCII码";
CM_ SG_ 2417749628 S2P_Cfg11_HW_Ver_Byte10_60 "CSC硬件版本号Byte10对应的ASCII码";
CM_ SG_ 2417749628 S2P_Cfg11_HW_Ver_Byte11_60 "CSC硬件版本号Byte11对应的ASCII码";
CM_ SG_ 2417749628 S2P_Cfg11_HW_Ver_Byte12_60 "CSC硬件版本号Byte12对应的ASCII码";
CM_ SG_ 2417749628 S2P_Cfg11_HW_Ver_Byte13_60 "CSC硬件版本号Byte13对应的ASCII码";
CM_ SG_ 2417749628 S2P_Cfg11_HW_Ver_Byte14_60 "CSC硬件版本号Byte14对应的ASCII码";
CM_ SG_ 2417749628 S2P_Cfg11_HW_Ver_Byte15_60 "CSC硬件版本号Byte15对应的ASCII码";
CM_ SG_ 2417749628 S2P_Cfg11_HW_Ver_Byte16_60 "CSC硬件版本号最高字节Byte16对应的ASCII码";
VERSION ""

NS_ :

BS_:

BU_: MBMU PC SBMU IMM ETH DCDC LEMS

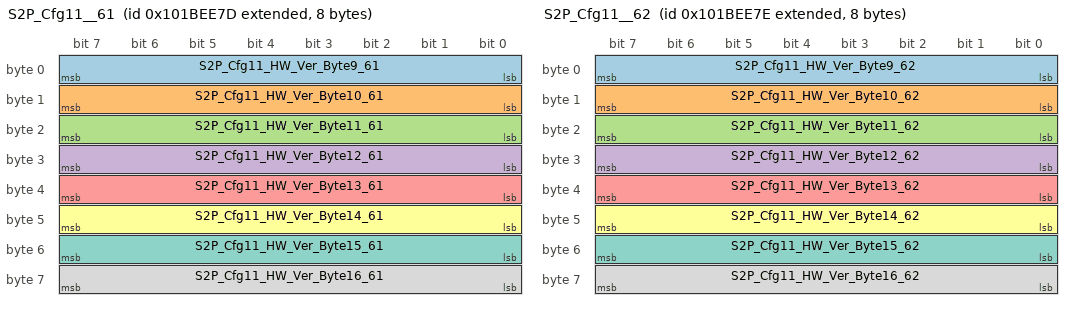
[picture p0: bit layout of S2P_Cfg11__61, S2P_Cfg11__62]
BO_ 2417749629 S2P_Cfg11__61: 8 SBMU
 SG_ S2P_Cfg11_HW_Ver_Byte9_61 : 0|8@1+ (1,0) [0|255] ""  PC
 SG_ S2P_Cfg11_HW_Ver_Byte10_61 : 8|8@1+ (1,0) [0|255] ""  PC
 SG_ S2P_Cfg11_HW_Ver_Byte11_61 : 16|8@1+ (1,0) [0|255] ""  PC
 SG_ S2P_Cfg11_HW_Ver_Byte12_61 : 24|8@1+ (1,0) [0|255] ""  PC
 SG_ S2P_Cfg11_HW_Ver_Byte13_61 : 32|8@1+ (1,0) [0|255] ""  PC
 SG_ S2P_Cfg11_HW_Ver_Byte14_61 : 40|8@1+ (1,0) [0|255] ""  PC
 SG_ S2P_Cfg11_HW_Ver_Byte15_61 : 48|8@1+ (1,0) [0|255] ""  PC
 SG_ S2P_Cfg11_HW_Ver_Byte16_61 : 56|8@1+ (1,0) [0|255] ""  PC

BO_ 2417749630 S2P_Cfg11__62: 8 SBMU
 SG_ S2P_Cfg11_HW_Ver_Byte9_62 : 0|8@1+ (1,0) [0|255] ""  PC
 SG_ S2P_Cfg11_HW_Ver_Byte10_62 : 8|8@1+ (1,0) [0|255] ""  PC
 SG_ S2P_Cfg11_HW_Ver_Byte11_62 : 16|8@1+ (1,0) [0|255] ""  PC
 SG_ S2P_Cfg11_HW_Ver_Byte12_62 : 24|8@1+ (1,0) [0|255] ""  PC
 SG_ S2P_Cfg11_HW_Ver_Byte13_62 : 32|8@1+ (1,0) [0|255] ""  PC
 SG_ S2P_Cfg11_HW_Ver_Byte14_62 : 40|8@1+ (1,0) [0|255] ""  PC
 SG_ S2P_Cfg11_HW_Ver_Byte15_62 : 48|8@1+ (1,0) [0|255] ""  PC
 SG_ S2P_Cfg11_HW_Ver_Byte16_62 : 56|8@1+ (1,0) [0|255] ""  PC

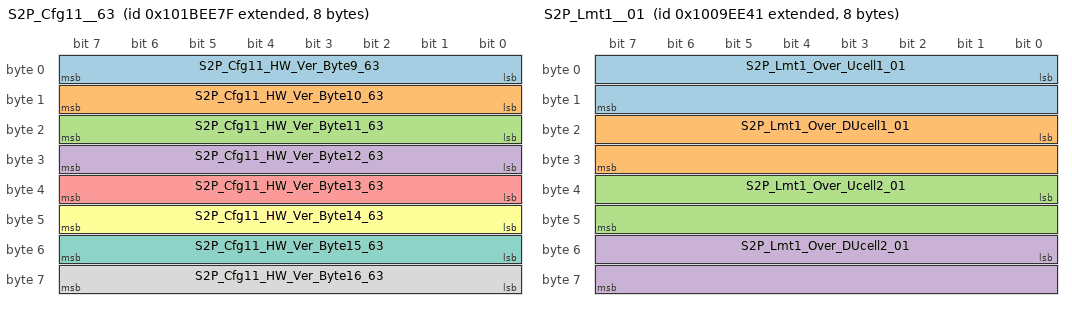
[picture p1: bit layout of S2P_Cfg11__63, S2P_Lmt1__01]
BO_ 2417749631 S2P_Cfg11__63: 8 SBMU
 SG_ S2P_Cfg11_HW_Ver_Byte9_63 : 0|8@1+ (1,0) [0|255] ""  PC
 SG_ S2P_Cfg11_HW_Ver_Byte10_63 : 8|8@1+ (1,0) [0|255] ""  PC
 SG_ S2P_Cfg11_HW_Ver_Byte11_63 : 16|8@1+ (1,0) [0|255] ""  PC
 SG_ S2P_Cfg11_HW_Ver_Byte12_63 : 24|8@1+ (1,0) [0|255] ""  PC
 SG_ S2P_Cfg11_HW_Ver_Byte13_63 : 32|8@1+ (1,0) [0|255] ""  PC
 SG_ S2P_Cfg11_HW_Ver_Byte14_63 : 40|8@1+ (1,0) [0|255] ""  PC
 SG_ S2P_Cfg11_HW_Ver_Byte15_63 : 48|8@1+ (1,0) [0|255] ""  PC
 SG_ S2P_Cfg11_HW_Ver_Byte16_63 : 56|8@1+ (1,0) [0|255] ""  PC

BO_ 2416569921 S2P_Lmt1__01: 8 SBMU
 SG_ S2P_Lmt1_Over_Ucell1_01 : 0|16@1+ (1,0) [0|65535] "mV"  PC
 SG_ S2P_Lmt1_Over_DUcell1_01 : 16|16@1+ (1,0) [0|65535] "mV"  PC
 SG_ S2P_Lmt1_Over_Ucell2_01 : 32|16@1+ (1,0) [0|65535] "mV"  PC
 SG_ S2P_Lmt1_Over_DUcell2_01 : 48|16@1+ (1,0) [0|65535] "mV"  PC

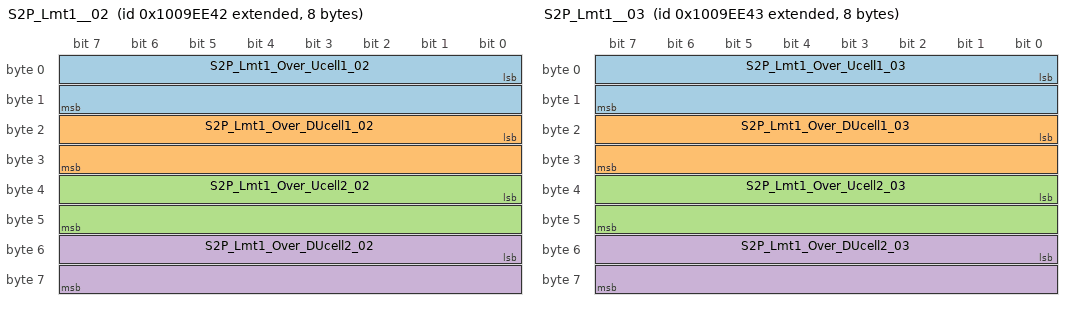
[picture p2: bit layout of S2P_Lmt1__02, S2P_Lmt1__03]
BO_ 2416569922 S2P_Lmt1__02: 8 SBMU
 SG_ S2P_Lmt1_Over_Ucell1_02 : 0|16@1+ (1,0) [0|65535] "mV"  PC
 SG_ S2P_Lmt1_Over_DUcell1_02 : 16|16@1+ (1,0) [0|65535] "mV"  PC
 SG_ S2P_Lmt1_Over_Ucell2_02 : 32|16@1+ (1,0) [0|65535] "mV"  PC
 SG_ S2P_Lmt1_Over_DUcell2_02 : 48|16@1+ (1,0) [0|65535] "mV"  PC

BO_ 2416569923 S2P_Lmt1__03: 8 SBMU
 SG_ S2P_Lmt1_Over_Ucell1_03 : 0|16@1+ (1,0) [0|65535] "mV"  PC
 SG_ S2P_Lmt1_Over_DUcell1_03 : 16|16@1+ (1,0) [0|65535] "mV"  PC
 SG_ S2P_Lmt1_Over_Ucell2_03 : 32|16@1+ (1,0) [0|65535] "mV"  PC
 SG_ S2P_Lmt1_Over_DUcell2_03 : 48|16@1+ (1,0) [0|65535] "mV"  PC

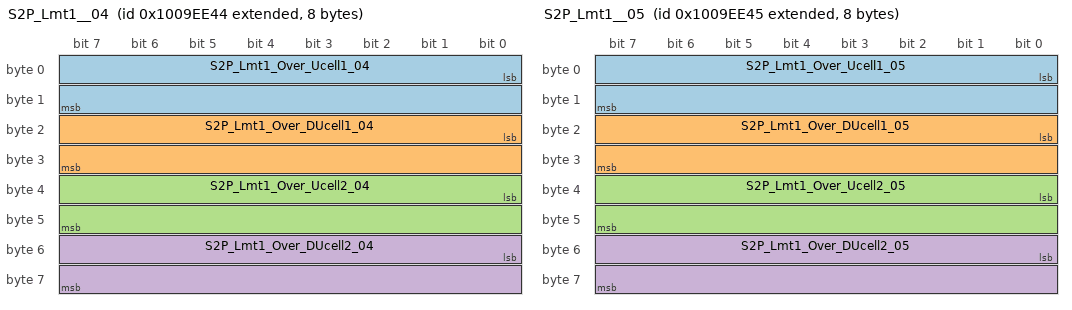
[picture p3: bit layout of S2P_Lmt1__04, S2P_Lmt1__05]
BO_ 2416569924 S2P_Lmt1__04: 8 SBMU
 SG_ S2P_Lmt1_Over_Ucell1_04 : 0|16@1+ (1,0) [0|65535] "mV"  PC
 SG_ S2P_Lmt1_Over_DUcell1_04 : 16|16@1+ (1,0) [0|65535] "mV"  PC
 SG_ S2P_Lmt1_Over_Ucell2_04 : 32|16@1+ (1,0) [0|65535] "mV"  PC
 SG_ S2P_Lmt1_Over_DUcell2_04 : 48|16@1+ (1,0) [0|65535] "mV"  PC

BO_ 2416569925 S2P_Lmt1__05: 8 SBMU
 SG_ S2P_Lmt1_Over_Ucell1_05 : 0|16@1+ (1,0) [0|65535] "mV"  PC
 SG_ S2P_Lmt1_Over_DUcell1_05 : 16|16@1+ (1,0) [0|65535] "mV"  PC
 SG_ S2P_Lmt1_Over_Ucell2_05 : 32|16@1+ (1,0) [0|65535] "mV"  PC
 SG_ S2P_Lmt1_Over_DUcell2_05 : 48|16@1+ (1,0) [0|65535] "mV"  PC

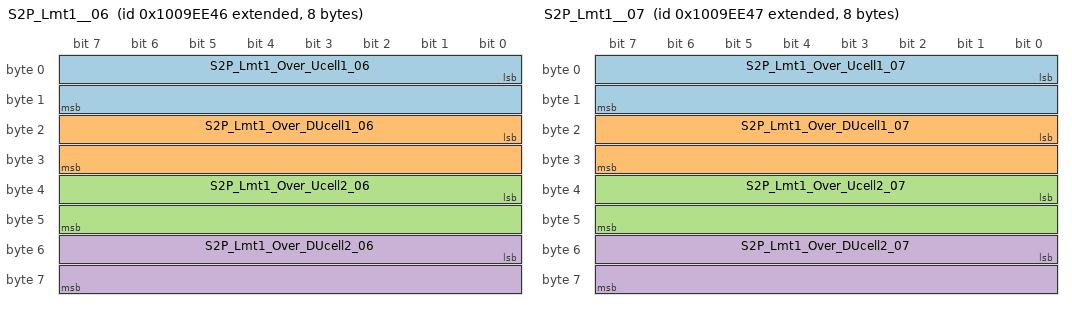
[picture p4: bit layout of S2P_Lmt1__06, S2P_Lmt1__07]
BO_ 2416569926 S2P_Lmt1__06: 8 SBMU
 SG_ S2P_Lmt1_Over_Ucell1_06 : 0|16@1+ (1,0) [0|65535] "mV"  PC
 SG_ S2P_Lmt1_Over_DUcell1_06 : 16|16@1+ (1,0) [0|65535] "mV"  PC
 SG_ S2P_Lmt1_Over_Ucell2_06 : 32|16@1+ (1,0) [0|65535] "mV"  PC
 SG_ S2P_Lmt1_Over_DUcell2_06 : 48|16@1+ (1,0) [0|65535] "mV"  PC

BO_ 2416569927 S2P_Lmt1__07: 8 SBMU
 SG_ S2P_Lmt1_Over_Ucell1_07 : 0|16@1+ (1,0) [0|65535] "mV"  PC
 SG_ S2P_Lmt1_Over_DUcell1_07 : 16|16@1+ (1,0) [0|65535] "mV"  PC
 SG_ S2P_Lmt1_Over_Ucell2_07 : 32|16@1+ (1,0) [0|65535] "mV"  PC
 SG_ S2P_Lmt1_Over_DUcell2_07 : 48|16@1+ (1,0) [0|65535] "mV"  PC

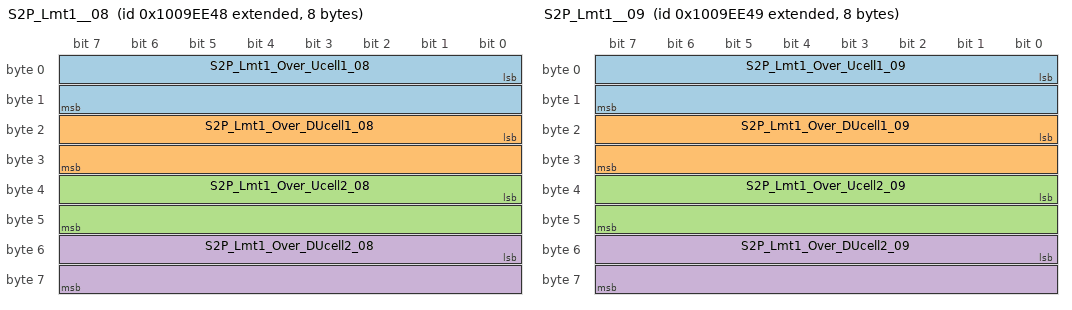
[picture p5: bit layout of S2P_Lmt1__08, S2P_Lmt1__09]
BO_ 2416569928 S2P_Lmt1__08: 8 SBMU
 SG_ S2P_Lmt1_Over_Ucell1_08 : 0|16@1+ (1,0) [0|65535] "mV"  PC
 SG_ S2P_Lmt1_Over_DUcell1_08 : 16|16@1+ (1,0) [0|65535] "mV"  PC
 SG_ S2P_Lmt1_Over_Ucell2_08 : 32|16@1+ (1,0) [0|65535] "mV"  PC
 SG_ S2P_Lmt1_Over_DUcell2_08 : 48|16@1+ (1,0) [0|65535] "mV"  PC

BO_ 2416569929 S2P_Lmt1__09: 8 SBMU
 SG_ S2P_Lmt1_Over_Ucell1_09 : 0|16@1+ (1,0) [0|65535] "mV"  PC
 SG_ S2P_Lmt1_Over_DUcell1_09 : 16|16@1+ (1,0) [0|65535] "mV"  PC
 SG_ S2P_Lmt1_Over_Ucell2_09 : 32|16@1+ (1,0) [0|65535] "mV"  PC
 SG_ S2P_Lmt1_Over_DUcell2_09 : 48|16@1+ (1,0) [0|65535] "mV"  PC

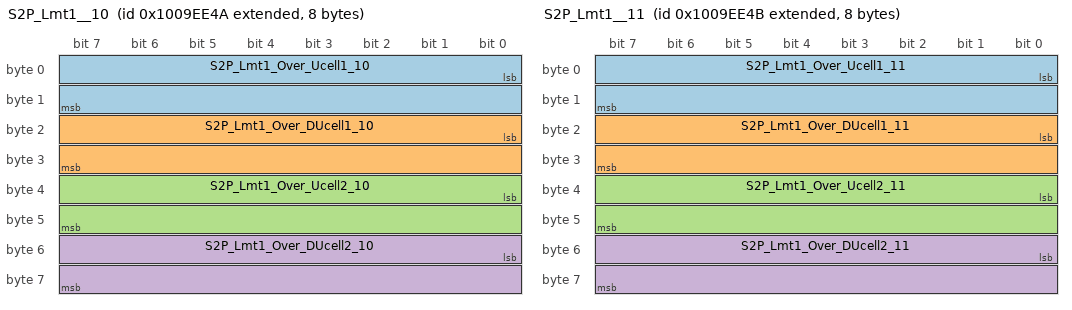
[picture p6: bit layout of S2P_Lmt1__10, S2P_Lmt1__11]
BO_ 2416569930 S2P_Lmt1__10: 8 SBMU
 SG_ S2P_Lmt1_Over_Ucell1_10 : 0|16@1+ (1,0) [0|65535] "mV"  PC
 SG_ S2P_Lmt1_Over_DUcell1_10 : 16|16@1+ (1,0) [0|65535] "mV"  PC
 SG_ S2P_Lmt1_Over_Ucell2_10 : 32|16@1+ (1,0) [0|65535] "mV"  PC
 SG_ S2P_Lmt1_Over_DUcell2_10 : 48|16@1+ (1,0) [0|65535] "mV"  PC

BO_ 2416569931 S2P_Lmt1__11: 8 SBMU
 SG_ S2P_Lmt1_Over_Ucell1_11 : 0|16@1+ (1,0) [0|65535] "mV"  PC
 SG_ S2P_Lmt1_Over_DUcell1_11 : 16|16@1+ (1,0) [0|65535] "mV"  PC
 SG_ S2P_Lmt1_Over_Ucell2_11 : 32|16@1+ (1,0) [0|65535] "mV"  PC
 SG_ S2P_Lmt1_Over_DUcell2_11 : 48|16@1+ (1,0) [0|65535] "mV"  PC

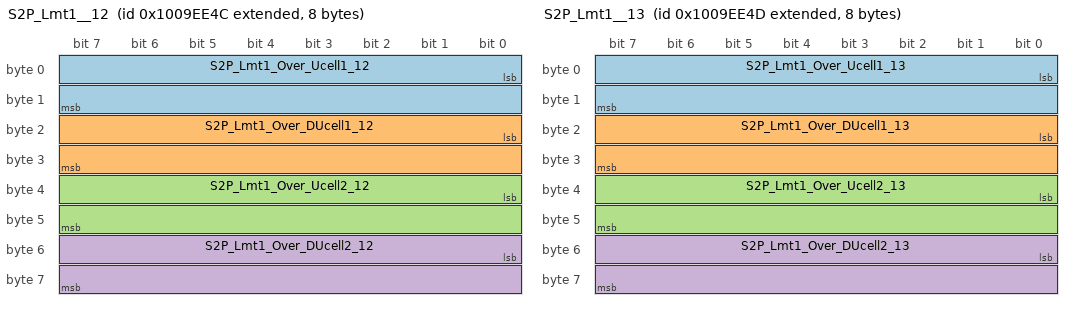
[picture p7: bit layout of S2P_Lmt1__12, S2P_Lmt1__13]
BO_ 2416569932 S2P_Lmt1__12: 8 SBMU
 SG_ S2P_Lmt1_Over_Ucell1_12 : 0|16@1+ (1,0) [0|65535] "mV"  PC
 SG_ S2P_Lmt1_Over_DUcell1_12 : 16|16@1+ (1,0) [0|65535] "mV"  PC
 SG_ S2P_Lmt1_Over_Ucell2_12 : 32|16@1+ (1,0) [0|65535] "mV"  PC
 SG_ S2P_Lmt1_Over_DUcell2_12 : 48|16@1+ (1,0) [0|65535] "mV"  PC

BO_ 2416569933 S2P_Lmt1__13: 8 SBMU
 SG_ S2P_Lmt1_Over_Ucell1_13 : 0|16@1+ (1,0) [0|65535] "mV"  PC
 SG_ S2P_Lmt1_Over_DUcell1_13 : 16|16@1+ (1,0) [0|65535] "mV"  PC
 SG_ S2P_Lmt1_Over_Ucell2_13 : 32|16@1+ (1,0) [0|65535] "mV"  PC
 SG_ S2P_Lmt1_Over_DUcell2_13 : 48|16@1+ (1,0) [0|65535] "mV"  PC

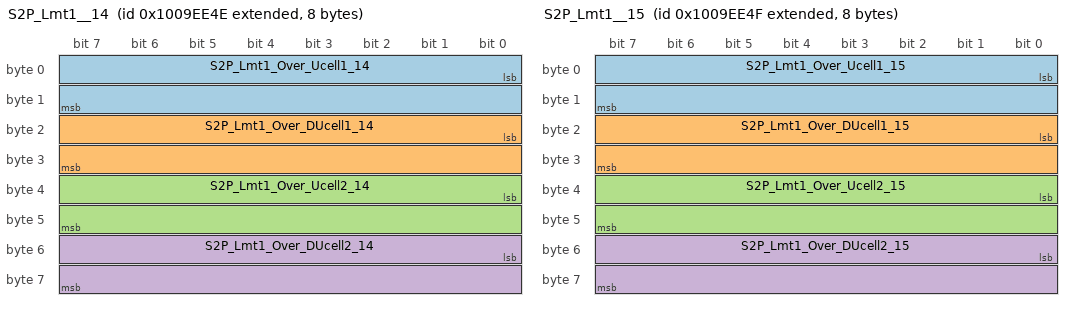
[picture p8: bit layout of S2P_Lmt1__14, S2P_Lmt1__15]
BO_ 2416569934 S2P_Lmt1__14: 8 SBMU
 SG_ S2P_Lmt1_Over_Ucell1_14 : 0|16@1+ (1,0) [0|65535] "mV"  PC
 SG_ S2P_Lmt1_Over_DUcell1_14 : 16|16@1+ (1,0) [0|65535] "mV"  PC
 SG_ S2P_Lmt1_Over_Ucell2_14 : 32|16@1+ (1,0) [0|65535] "mV"  PC
 SG_ S2P_Lmt1_Over_DUcell2_14 : 48|16@1+ (1,0) [0|65535] "mV"  PC

BO_ 2416569935 S2P_Lmt1__15: 8 SBMU
 SG_ S2P_Lmt1_Over_Ucell1_15 : 0|16@1+ (1,0) [0|65535] "mV"  PC
 SG_ S2P_Lmt1_Over_DUcell1_15 : 16|16@1+ (1,0) [0|65535] "mV"  PC
 SG_ S2P_Lmt1_Over_Ucell2_15 : 32|16@1+ (1,0) [0|65535] "mV"  PC
 SG_ S2P_Lmt1_Over_DUcell2_15 : 48|16@1+ (1,0) [0|65535] "mV"  PC

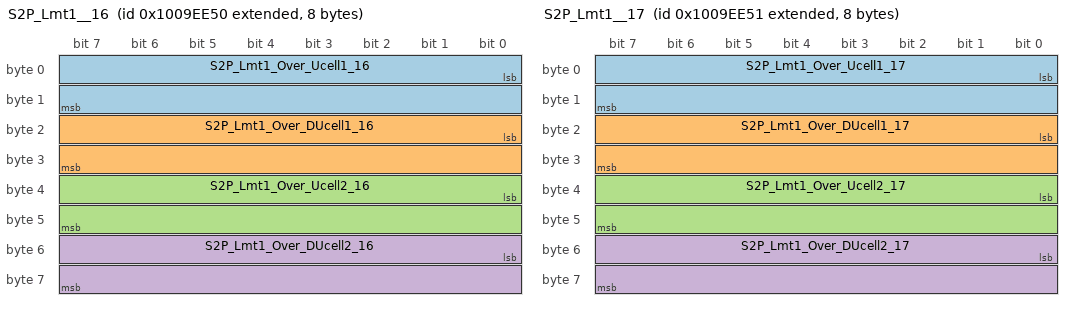
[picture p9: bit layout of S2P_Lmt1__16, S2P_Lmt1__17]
BO_ 2416569936 S2P_Lmt1__16: 8 SBMU
 SG_ S2P_Lmt1_Over_Ucell1_16 : 0|16@1+ (1,0) [0|65535] "mV"  PC
 SG_ S2P_Lmt1_Over_DUcell1_16 : 16|16@1+ (1,0) [0|65535] "mV"  PC
 SG_ S2P_Lmt1_Over_Ucell2_16 : 32|16@1+ (1,0) [0|65535] "mV"  PC
 SG_ S2P_Lmt1_Over_DUcell2_16 : 48|16@1+ (1,0) [0|65535] "mV"  PC

BO_ 2416569937 S2P_Lmt1__17: 8 SBMU
 SG_ S2P_Lmt1_Over_Ucell1_17 : 0|16@1+ (1,0) [0|65535] "mV"  PC
 SG_ S2P_Lmt1_Over_DUcell1_17 : 16|16@1+ (1,0) [0|65535] "mV"  PC
 SG_ S2P_Lmt1_Over_Ucell2_17 : 32|16@1+ (1,0) [0|65535] "mV"  PC
 SG_ S2P_Lmt1_Over_DUcell2_17 : 48|16@1+ (1,0) [0|65535] "mV"  PC

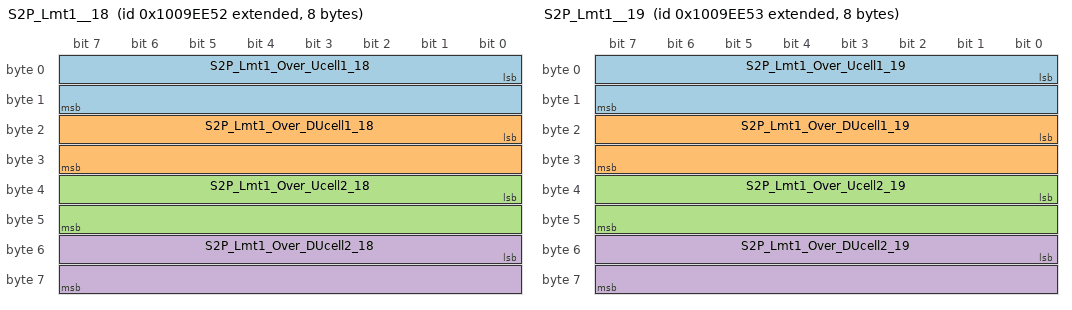
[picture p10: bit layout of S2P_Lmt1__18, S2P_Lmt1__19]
BO_ 2416569938 S2P_Lmt1__18: 8 SBMU
 SG_ S2P_Lmt1_Over_Ucell1_18 : 0|16@1+ (1,0) [0|65535] "mV"  PC
 SG_ S2P_Lmt1_Over_DUcell1_18 : 16|16@1+ (1,0) [0|65535] "mV"  PC
 SG_ S2P_Lmt1_Over_Ucell2_18 : 32|16@1+ (1,0) [0|65535] "mV"  PC
 SG_ S2P_Lmt1_Over_DUcell2_18 : 48|16@1+ (1,0) [0|65535] "mV"  PC

BO_ 2416569939 S2P_Lmt1__19: 8 SBMU
 SG_ S2P_Lmt1_Over_Ucell1_19 : 0|16@1+ (1,0) [0|65535] "mV"  PC
 SG_ S2P_Lmt1_Over_DUcell1_19 : 16|16@1+ (1,0) [0|65535] "mV"  PC
 SG_ S2P_Lmt1_Over_Ucell2_19 : 32|16@1+ (1,0) [0|65535] "mV"  PC
 SG_ S2P_Lmt1_Over_DUcell2_19 : 48|16@1+ (1,0) [0|65535] "mV"  PC

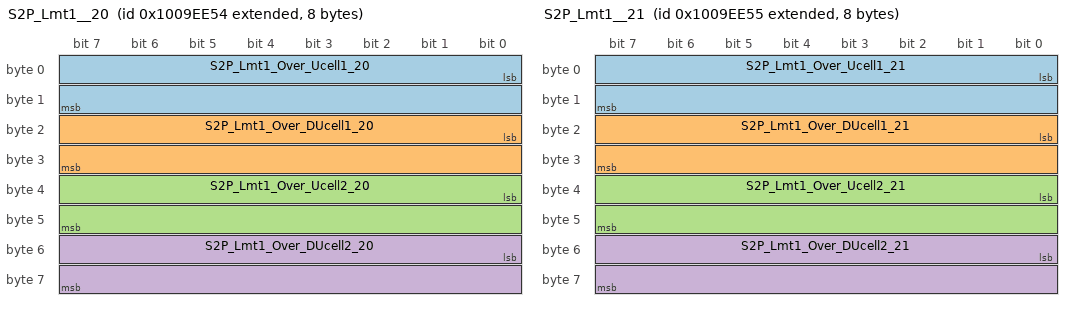
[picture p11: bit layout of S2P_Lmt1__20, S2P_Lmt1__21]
BO_ 2416569940 S2P_Lmt1__20: 8 SBMU
 SG_ S2P_Lmt1_Over_Ucell1_20 : 0|16@1+ (1,0) [0|65535] "mV"  PC
 SG_ S2P_Lmt1_Over_DUcell1_20 : 16|16@1+ (1,0) [0|65535] "mV"  PC
 SG_ S2P_Lmt1_Over_Ucell2_20 : 32|16@1+ (1,0) [0|65535] "mV"  PC
 SG_ S2P_Lmt1_Over_DUcell2_20 : 48|16@1+ (1,0) [0|65535] "mV"  PC

BO_ 2416569941 S2P_Lmt1__21: 8 SBMU
 SG_ S2P_Lmt1_Over_Ucell1_21 : 0|16@1+ (1,0) [0|65535] "mV"  PC
 SG_ S2P_Lmt1_Over_DUcell1_21 : 16|16@1+ (1,0) [0|65535] "mV"  PC
 SG_ S2P_Lmt1_Over_Ucell2_21 : 32|16@1+ (1,0) [0|65535] "mV"  PC
 SG_ S2P_Lmt1_Over_DUcell2_21 : 48|16@1+ (1,0) [0|65535] "mV"  PC

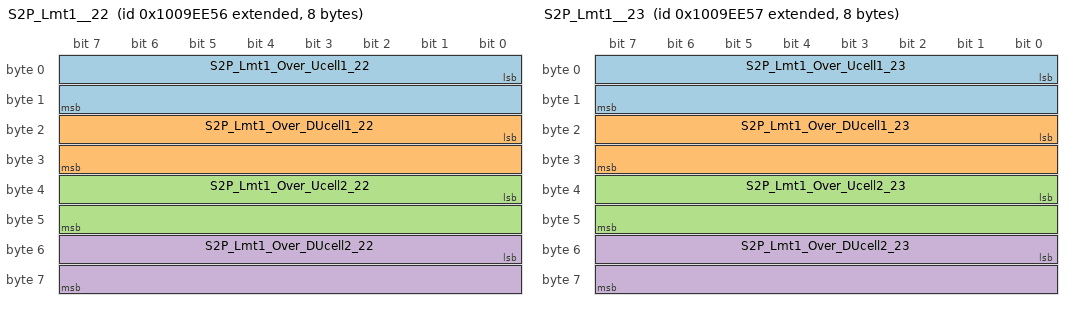
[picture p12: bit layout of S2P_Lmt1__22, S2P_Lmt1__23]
BO_ 2416569942 S2P_Lmt1__22: 8 SBMU
 SG_ S2P_Lmt1_Over_Ucell1_22 : 0|16@1+ (1,0) [0|65535] "mV"  PC
 SG_ S2P_Lmt1_Over_DUcell1_22 : 16|16@1+ (1,0) [0|65535] "mV"  PC
 SG_ S2P_Lmt1_Over_Ucell2_22 : 32|16@1+ (1,0) [0|65535] "mV"  PC
 SG_ S2P_Lmt1_Over_DUcell2_22 : 48|16@1+ (1,0) [0|65535] "mV"  PC

BO_ 2416569943 S2P_Lmt1__23: 8 SBMU
 SG_ S2P_Lmt1_Over_Ucell1_23 : 0|16@1+ (1,0) [0|65535] "mV"  PC
 SG_ S2P_Lmt1_Over_DUcell1_23 : 16|16@1+ (1,0) [0|65535] "mV"  PC
 SG_ S2P_Lmt1_Over_Ucell2_23 : 32|16@1+ (1,0) [0|65535] "mV"  PC
 SG_ S2P_Lmt1_Over_DUcell2_23 : 48|16@1+ (1,0) [0|65535] "mV"  PC

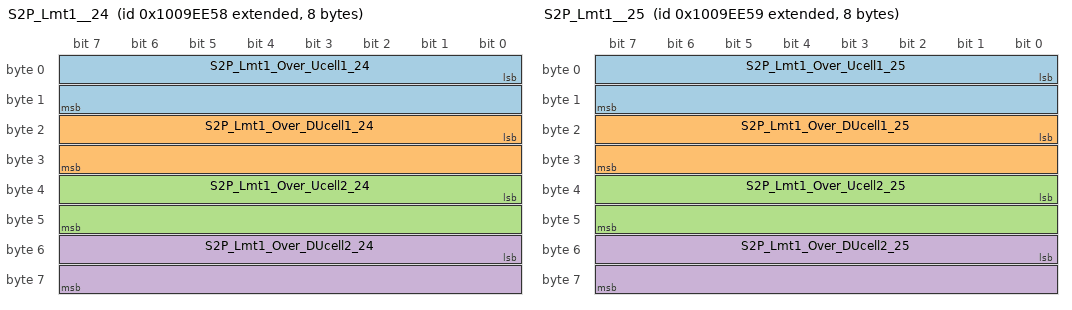
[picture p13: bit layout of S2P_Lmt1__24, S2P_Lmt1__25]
BO_ 2416569944 S2P_Lmt1__24: 8 SBMU
 SG_ S2P_Lmt1_Over_Ucell1_24 : 0|16@1+ (1,0) [0|65535] "mV"  PC
 SG_ S2P_Lmt1_Over_DUcell1_24 : 16|16@1+ (1,0) [0|65535] "mV"  PC
 SG_ S2P_Lmt1_Over_Ucell2_24 : 32|16@1+ (1,0) [0|65535] "mV"  PC
 SG_ S2P_Lmt1_Over_DUcell2_24 : 48|16@1+ (1,0) [0|65535] "mV"  PC

BO_ 2416569945 S2P_Lmt1__25: 8 SBMU
 SG_ S2P_Lmt1_Over_Ucell1_25 : 0|16@1+ (1,0) [0|65535] "mV"  PC
 SG_ S2P_Lmt1_Over_DUcell1_25 : 16|16@1+ (1,0) [0|65535] "mV"  PC
 SG_ S2P_Lmt1_Over_Ucell2_25 : 32|16@1+ (1,0) [0|65535] "mV"  PC
 SG_ S2P_Lmt1_Over_DUcell2_25 : 48|16@1+ (1,0) [0|65535] "mV"  PC

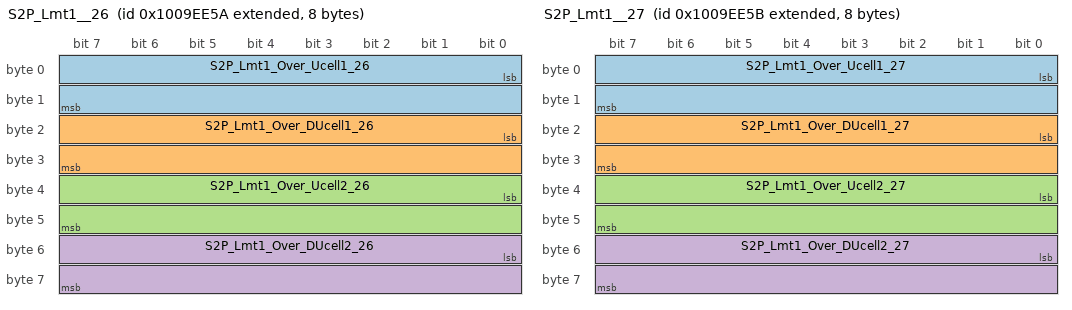
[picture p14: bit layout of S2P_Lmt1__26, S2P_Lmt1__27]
BO_ 2416569946 S2P_Lmt1__26: 8 SBMU
 SG_ S2P_Lmt1_Over_Ucell1_26 : 0|16@1+ (1,0) [0|65535] "mV"  PC
 SG_ S2P_Lmt1_Over_DUcell1_26 : 16|16@1+ (1,0) [0|65535] "mV"  PC
 SG_ S2P_Lmt1_Over_Ucell2_26 : 32|16@1+ (1,0) [0|65535] "mV"  PC
 SG_ S2P_Lmt1_Over_DUcell2_26 : 48|16@1+ (1,0) [0|65535] "mV"  PC

BO_ 2416569947 S2P_Lmt1__27: 8 SBMU
 SG_ S2P_Lmt1_Over_Ucell1_27 : 0|16@1+ (1,0) [0|65535] "mV"  PC
 SG_ S2P_Lmt1_Over_DUcell1_27 : 16|16@1+ (1,0) [0|65535] "mV"  PC
 SG_ S2P_Lmt1_Over_Ucell2_27 : 32|16@1+ (1,0) [0|65535] "mV"  PC
 SG_ S2P_Lmt1_Over_DUcell2_27 : 48|16@1+ (1,0) [0|65535] "mV"  PC

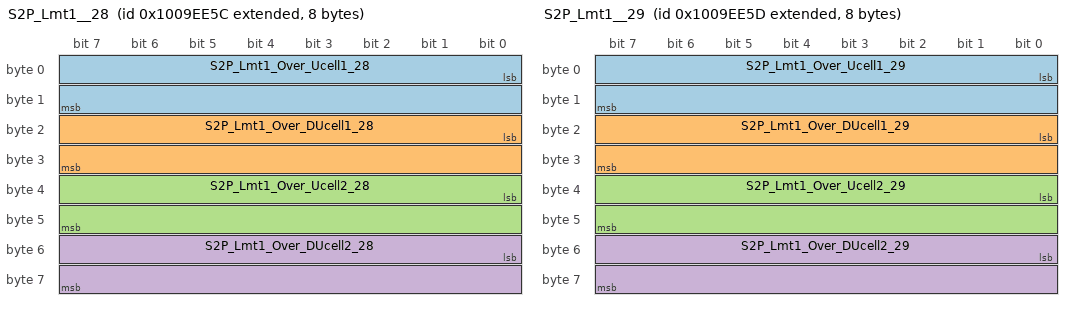
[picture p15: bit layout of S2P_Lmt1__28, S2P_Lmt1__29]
BO_ 2416569948 S2P_Lmt1__28: 8 SBMU
 SG_ S2P_Lmt1_Over_Ucell1_28 : 0|16@1+ (1,0) [0|65535] "mV"  PC
 SG_ S2P_Lmt1_Over_DUcell1_28 : 16|16@1+ (1,0) [0|65535] "mV"  PC
 SG_ S2P_Lmt1_Over_Ucell2_28 : 32|16@1+ (1,0) [0|65535] "mV"  PC
 SG_ S2P_Lmt1_Over_DUcell2_28 : 48|16@1+ (1,0) [0|65535] "mV"  PC

BO_ 2416569949 S2P_Lmt1__29: 8 SBMU
 SG_ S2P_Lmt1_Over_Ucell1_29 : 0|16@1+ (1,0) [0|65535] "mV"  PC
 SG_ S2P_Lmt1_Over_DUcell1_29 : 16|16@1+ (1,0) [0|65535] "mV"  PC
 SG_ S2P_Lmt1_Over_Ucell2_29 : 32|16@1+ (1,0) [0|65535] "mV"  PC
 SG_ S2P_Lmt1_Over_DUcell2_29 : 48|16@1+ (1,0) [0|65535] "mV"  PC

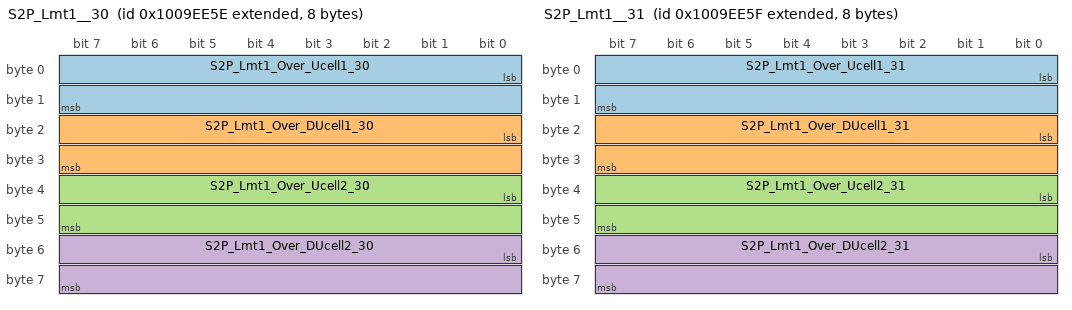
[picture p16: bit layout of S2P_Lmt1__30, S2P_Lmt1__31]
BO_ 2416569950 S2P_Lmt1__30: 8 SBMU
 SG_ S2P_Lmt1_Over_Ucell1_30 : 0|16@1+ (1,0) [0|65535] "mV"  PC
 SG_ S2P_Lmt1_Over_DUcell1_30 : 16|16@1+ (1,0) [0|65535] "mV"  PC
 SG_ S2P_Lmt1_Over_Ucell2_30 : 32|16@1+ (1,0) [0|65535] "mV"  PC
 SG_ S2P_Lmt1_Over_DUcell2_30 : 48|16@1+ (1,0) [0|65535] "mV"  PC

BO_ 2416569951 S2P_Lmt1__31: 8 SBMU
 SG_ S2P_Lmt1_Over_Ucell1_31 : 0|16@1+ (1,0) [0|65535] "mV"  PC
 SG_ S2P_Lmt1_Over_DUcell1_31 : 16|16@1+ (1,0) [0|65535] "mV"  PC
 SG_ S2P_Lmt1_Over_Ucell2_31 : 32|16@1+ (1,0) [0|65535] "mV"  PC
 SG_ S2P_Lmt1_Over_DUcell2_31 : 48|16@1+ (1,0) [0|65535] "mV"  PC

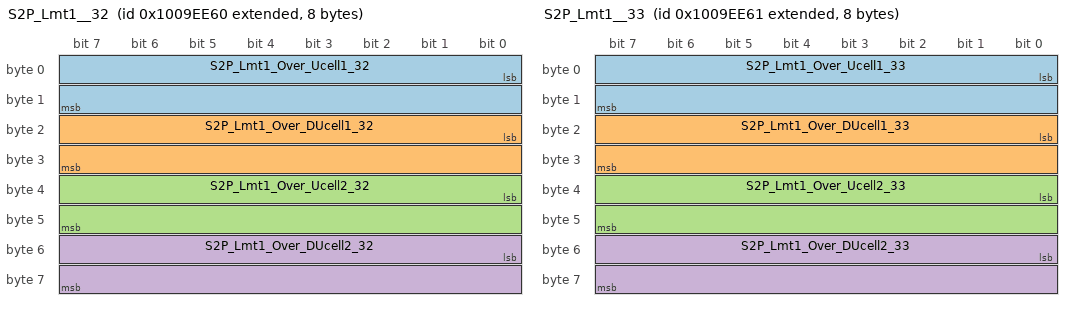
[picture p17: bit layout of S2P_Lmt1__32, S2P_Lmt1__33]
BO_ 2416569952 S2P_Lmt1__32: 8 SBMU
 SG_ S2P_Lmt1_Over_Ucell1_32 : 0|16@1+ (1,0) [0|65535] "mV"  PC
 SG_ S2P_Lmt1_Over_DUcell1_32 : 16|16@1+ (1,0) [0|65535] "mV"  PC
 SG_ S2P_Lmt1_Over_Ucell2_32 : 32|16@1+ (1,0) [0|65535] "mV"  PC
 SG_ S2P_Lmt1_Over_DUcell2_32 : 48|16@1+ (1,0) [0|65535] "mV"  PC

BO_ 2416569953 S2P_Lmt1__33: 8 SBMU
 SG_ S2P_Lmt1_Over_Ucell1_33 : 0|16@1+ (1,0) [0|65535] "mV"  PC
 SG_ S2P_Lmt1_Over_DUcell1_33 : 16|16@1+ (1,0) [0|65535] "mV"  PC
 SG_ S2P_Lmt1_Over_Ucell2_33 : 32|16@1+ (1,0) [0|65535] "mV"  PC
 SG_ S2P_Lmt1_Over_DUcell2_33 : 48|16@1+ (1,0) [0|65535] "mV"  PC

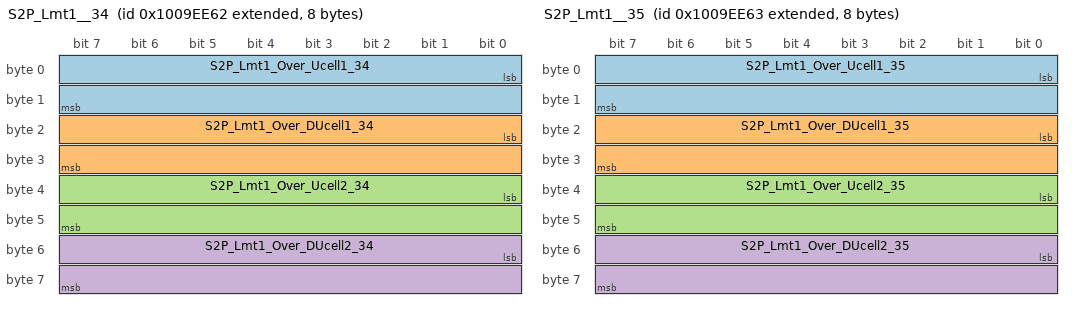
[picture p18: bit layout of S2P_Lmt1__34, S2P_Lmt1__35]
BO_ 2416569954 S2P_Lmt1__34: 8 SBMU
 SG_ S2P_Lmt1_Over_Ucell1_34 : 0|16@1+ (1,0) [0|65535] "mV"  PC
 SG_ S2P_Lmt1_Over_DUcell1_34 : 16|16@1+ (1,0) [0|65535] "mV"  PC
 SG_ S2P_Lmt1_Over_Ucell2_34 : 32|16@1+ (1,0) [0|65535] "mV"  PC
 SG_ S2P_Lmt1_Over_DUcell2_34 : 48|16@1+ (1,0) [0|65535] "mV"  PC

BO_ 2416569955 S2P_Lmt1__35: 8 SBMU
 SG_ S2P_Lmt1_Over_Ucell1_35 : 0|16@1+ (1,0) [0|65535] "mV"  PC
 SG_ S2P_Lmt1_Over_DUcell1_35 : 16|16@1+ (1,0) [0|65535] "mV"  PC
 SG_ S2P_Lmt1_Over_Ucell2_35 : 32|16@1+ (1,0) [0|65535] "mV"  PC
 SG_ S2P_Lmt1_Over_DUcell2_35 : 48|16@1+ (1,0) [0|65535] "mV"  PC

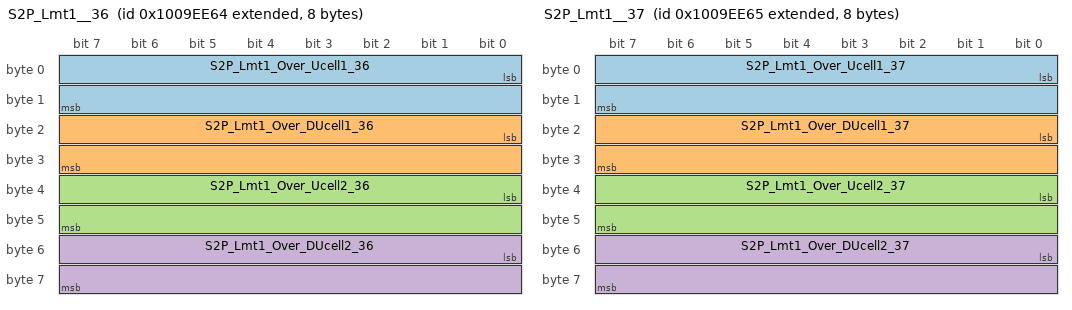
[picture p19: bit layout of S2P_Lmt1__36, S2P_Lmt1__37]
BO_ 2416569956 S2P_Lmt1__36: 8 SBMU
 SG_ S2P_Lmt1_Over_Ucell1_36 : 0|16@1+ (1,0) [0|65535] "mV"  PC
 SG_ S2P_Lmt1_Over_DUcell1_36 : 16|16@1+ (1,0) [0|65535] "mV"  PC
 SG_ S2P_Lmt1_Over_Ucell2_36 : 32|16@1+ (1,0) [0|65535] "mV"  PC
 SG_ S2P_Lmt1_Over_DUcell2_36 : 48|16@1+ (1,0) [0|65535] "mV"  PC

BO_ 2416569957 S2P_Lmt1__37: 8 SBMU
 SG_ S2P_Lmt1_Over_Ucell1_37 : 0|16@1+ (1,0) [0|65535] "mV"  PC
 SG_ S2P_Lmt1_Over_DUcell1_37 : 16|16@1+ (1,0) [0|65535] "mV"  PC
 SG_ S2P_Lmt1_Over_Ucell2_37 : 32|16@1+ (1,0) [0|65535] "mV"  PC
 SG_ S2P_Lmt1_Over_DUcell2_37 : 48|16@1+ (1,0) [0|65535] "mV"  PC

BO_ 2416569958 S2P_Lmt1__38: 8 SBMU
 SG_ S2P_Lmt1_Over_Ucell1_38 : 0|16@1+ (1,0) [0|65535] "mV"  PC
 SG_ S2P_Lmt1_Over_DUcell1_38 : 16|16@1+ (1,0) [0|65535] "mV"  PC
 SG_ S2P_Lmt1_Over_Ucell2_38 : 32|16@1+ (1,0) [0|65535] "mV"  PC
 SG_ S2P_Lmt1_Over_DUcell2_38 : 48|16@1+ (1,0) [0|65535] "mV"  PC

BO_ 2416569959 S2P_Lmt1__39: 8 SBMU
 SG_ S2P_Lmt1_Over_Ucell1_39 : 0|16@1+ (1,0) [0|65535] "mV"  PC
 SG_ S2P_Lmt1_Over_DUcell1_39 : 16|16@1+ (1,0) [0|65535] "mV"  PC
 SG_ S2P_Lmt1_Over_Ucell2_39 : 32|16@1+ (1,0) [0|65535] "mV"  PC
 SG_ S2P_Lmt1_Over_DUcell2_39 : 48|16@1+ (1,0) [0|65535] "mV"  PC

BO_ 2416569960 S2P_Lmt1__40: 8 SBMU
 SG_ S2P_Lmt1_Over_Ucell1_40 : 0|16@1+ (1,0) [0|65535] "mV"  PC
 SG_ S2P_Lmt1_Over_DUcell1_40 : 16|16@1+ (1,0) [0|65535] "mV"  PC
 SG_ S2P_Lmt1_Over_Ucell2_40 : 32|16@1+ (1,0) [0|65535] "mV"  PC
 SG_ S2P_Lmt1_Over_DUcell2_40 : 48|16@1+ (1,0) [0|65535] "mV"  PC

BO_ 2416569961 S2P_Lmt1__41: 8 SBMU
 SG_ S2P_Lmt1_Over_Ucell1_41 : 0|16@1+ (1,0) [0|65535] "mV"  PC
 SG_ S2P_Lmt1_Over_DUcell1_41 : 16|16@1+ (1,0) [0|65535] "mV"  PC
 SG_ S2P_Lmt1_Over_Ucell2_41 : 32|16@1+ (1,0) [0|65535] "mV"  PC
 SG_ S2P_Lmt1_Over_DUcell2_41 : 48|16@1+ (1,0) [0|65535] "mV"  PC

BO_ 2416569962 S2P_Lmt1__42: 8 SBMU
 SG_ S2P_Lmt1_Over_Ucell1_42 : 0|16@1+ (1,0) [0|65535] "mV"  PC
 SG_ S2P_Lmt1_Over_DUcell1_42 : 16|16@1+ (1,0) [0|65535] "mV"  PC
 SG_ S2P_Lmt1_Over_Ucell2_42 : 32|16@1+ (1,0) [0|65535] "mV"  PC
 SG_ S2P_Lmt1_Over_DUcell2_42 : 48|16@1+ (1,0) [0|65535] "mV"  PC

BO_ 2416569963 S2P_Lmt1__43: 8 SBMU
 SG_ S2P_Lmt1_Over_Ucell1_43 : 0|16@1+ (1,0) [0|65535] "mV"  PC
 SG_ S2P_Lmt1_Over_DUcell1_43 : 16|16@1+ (1,0) [0|65535] "mV"  PC
 SG_ S2P_Lmt1_Over_Ucell2_43 : 32|16@1+ (1,0) [0|65535] "mV"  PC
 SG_ S2P_Lmt1_Over_DUcell2_43 : 48|16@1+ (1,0) [0|65535] "mV"  PC

BO_ 2416569964 S2P_Lmt1__44: 8 SBMU
 SG_ S2P_Lmt1_Over_Ucell1_44 : 0|16@1+ (1,0) [0|65535] "mV"  PC
 SG_ S2P_Lmt1_Over_DUcell1_44 : 16|16@1+ (1,0) [0|65535] "mV"  PC
 SG_ S2P_Lmt1_Over_Ucell2_44 : 32|16@1+ (1,0) [0|65535] "mV"  PC
 SG_ S2P_Lmt1_Over_DUcell2_44 : 48|16@1+ (1,0) [0|65535] "mV"  PC

BO_ 2416569965 S2P_Lmt1__45: 8 SBMU
 SG_ S2P_Lmt1_Over_Ucell1_45 : 0|16@1+ (1,0) [0|65535] "mV"  PC
 SG_ S2P_Lmt1_Over_DUcell1_45 : 16|16@1+ (1,0) [0|65535] "mV"  PC
 SG_ S2P_Lmt1_Over_Ucell2_45 : 32|16@1+ (1,0) [0|65535] "mV"  PC
 SG_ S2P_Lmt1_Over_DUcell2_45 : 48|16@1+ (1,0) [0|65535] "mV"  PC

BO_ 2416569966 S2P_Lmt1__46: 8 SBMU
 SG_ S2P_Lmt1_Over_Ucell1_46 : 0|16@1+ (1,0) [0|65535] "mV"  PC
 SG_ S2P_Lmt1_Over_DUcell1_46 : 16|16@1+ (1,0) [0|65535] "mV"  PC
 SG_ S2P_Lmt1_Over_Ucell2_46 : 32|16@1+ (1,0) [0|65535] "mV"  PC
 SG_ S2P_Lmt1_Over_DUcell2_46 : 48|16@1+ (1,0) [0|65535] "mV"  PC

BO_ 2416569967 S2P_Lmt1__47: 8 SBMU
 SG_ S2P_Lmt1_Over_Ucell1_47 : 0|16@1+ (1,0) [0|65535] "mV"  PC
 SG_ S2P_Lmt1_Over_DUcell1_47 : 16|16@1+ (1,0) [0|65535] "mV"  PC
 SG_ S2P_Lmt1_Over_Ucell2_47 : 32|16@1+ (1,0) [0|65535] "mV"  PC
 SG_ S2P_Lmt1_Over_DUcell2_47 : 48|16@1+ (1,0) [0|65535] "mV"  PC

BO_ 2416569968 S2P_Lmt1__48: 8 SBMU
 SG_ S2P_Lmt1_Over_Ucell1_48 : 0|16@1+ (1,0) [0|65535] "mV"  PC
 SG_ S2P_Lmt1_Over_DUcell1_48 : 16|16@1+ (1,0) [0|65535] "mV"  PC
 SG_ S2P_Lmt1_Over_Ucell2_48 : 32|16@1+ (1,0) [0|65535] "mV"  PC
 SG_ S2P_Lmt1_Over_DUcell2_48 : 48|16@1+ (1,0) [0|65535] "mV"  PC

BO_ 2416569969 S2P_Lmt1__49: 8 SBMU
 SG_ S2P_Lmt1_Over_Ucell1_49 : 0|16@1+ (1,0) [0|65535] "mV"  PC
 SG_ S2P_Lmt1_Over_DUcell1_49 : 16|16@1+ (1,0) [0|65535] "mV"  PC
 SG_ S2P_Lmt1_Over_Ucell2_49 : 32|16@1+ (1,0) [0|65535] "mV"  PC
 SG_ S2P_Lmt1_Over_DUcell2_49 : 48|16@1+ (1,0) [0|65535] "mV"  PC

BO_ 2416569970 S2P_Lmt1__50: 8 SBMU
 SG_ S2P_Lmt1_Over_Ucell1_50 : 0|16@1+ (1,0) [0|65535] "mV"  PC
 SG_ S2P_Lmt1_Over_DUcell1_50 : 16|16@1+ (1,0) [0|65535] "mV"  PC
 SG_ S2P_Lmt1_Over_Ucell2_50 : 32|16@1+ (1,0) [0|65535] "mV"  PC
 SG_ S2P_Lmt1_Over_DUcell2_50 : 48|16@1+ (1,0) [0|65535] "mV"  PC

BO_ 2416569971 S2P_Lmt1__51: 8 SBMU
 SG_ S2P_Lmt1_Over_Ucell1_51 : 0|16@1+ (1,0) [0|65535] "mV"  PC
 SG_ S2P_Lmt1_Over_DUcell1_51 : 16|16@1+ (1,0) [0|65535] "mV"  PC
 SG_ S2P_Lmt1_Over_Ucell2_51 : 32|16@1+ (1,0) [0|65535] "mV"  PC
 SG_ S2P_Lmt1_Over_DUcell2_51 : 48|16@1+ (1,0) [0|65535] "mV"  PC

BO_ 2416569972 S2P_Lmt1__52: 8 SBMU
 SG_ S2P_Lmt1_Over_Ucell1_52 : 0|16@1+ (1,0) [0|65535] "mV"  PC
 SG_ S2P_Lmt1_Over_DUcell1_52 : 16|16@1+ (1,0) [0|65535] "mV"  PC
 SG_ S2P_Lmt1_Over_Ucell2_52 : 32|16@1+ (1,0) [0|65535] "mV"  PC
 SG_ S2P_Lmt1_Over_DUcell2_52 : 48|16@1+ (1,0) [0|65535] "mV"  PC

BO_ 2416569973 S2P_Lmt1__53: 8 SBMU
 SG_ S2P_Lmt1_Over_Ucell1_53 : 0|16@1+ (1,0) [0|65535] "mV"  PC
 SG_ S2P_Lmt1_Over_DUcell1_53 : 16|16@1+ (1,0) [0|65535] "mV"  PC
 SG_ S2P_Lmt1_Over_Ucell2_53 : 32|16@1+ (1,0) [0|65535] "mV"  PC
 SG_ S2P_Lmt1_Over_DUcell2_53 : 48|16@1+ (1,0) [0|65535] "mV"  PC

BO_ 2416569974 S2P_Lmt1__54: 8 SBMU
 SG_ S2P_Lmt1_Over_Ucell1_54 : 0|16@1+ (1,0) [0|65535] "mV"  PC
 SG_ S2P_Lmt1_Over_DUcell1_54 : 16|16@1+ (1,0) [0|65535] "mV"  PC
 SG_ S2P_Lmt1_Over_Ucell2_54 : 32|16@1+ (1,0) [0|65535] "mV"  PC
 SG_ S2P_Lmt1_Over_DUcell2_54 : 48|16@1+ (1,0) [0|65535] "mV"  PC

BO_ 2416569975 S2P_Lmt1__55: 8 SBMU
 SG_ S2P_Lmt1_Over_Ucell1_55 : 0|16@1+ (1,0) [0|65535] "mV"  PC
 SG_ S2P_Lmt1_Over_DUcell1_55 : 16|16@1+ (1,0) [0|65535] "mV"  PC
 SG_ S2P_Lmt1_Over_Ucell2_55 : 32|16@1+ (1,0) [0|65535] "mV"  PC
 SG_ S2P_Lmt1_Over_DUcell2_55 : 48|16@1+ (1,0) [0|65535] "mV"  PC

BO_ 2416569976 S2P_Lmt1__56: 8 SBMU
 SG_ S2P_Lmt1_Over_Ucell1_56 : 0|16@1+ (1,0) [0|65535] "mV"  PC
 SG_ S2P_Lmt1_Over_DUcell1_56 : 16|16@1+ (1,0) [0|65535] "mV"  PC
 SG_ S2P_Lmt1_Over_Ucell2_56 : 32|16@1+ (1,0) [0|65535] "mV"  PC
 SG_ S2P_Lmt1_Over_DUcell2_56 : 48|16@1+ (1,0) [0|65535] "mV"  PC

BO_ 2416569977 S2P_Lmt1__57: 8 SBMU
 SG_ S2P_Lmt1_Over_Ucell1_57 : 0|16@1+ (1,0) [0|65535] "mV"  PC
 SG_ S2P_Lmt1_Over_DUcell1_57 : 16|16@1+ (1,0) [0|65535] "mV"  PC
 SG_ S2P_Lmt1_Over_Ucell2_57 : 32|16@1+ (1,0) [0|65535] "mV"  PC
 SG_ S2P_Lmt1_Over_DUcell2_57 : 48|16@1+ (1,0) [0|65535] "mV"  PC

BO_ 2416569978 S2P_Lmt1__58: 8 SBMU
 SG_ S2P_Lmt1_Over_Ucell1_58 : 0|16@1+ (1,0) [0|65535] "mV"  PC
 SG_ S2P_Lmt1_Over_DUcell1_58 : 16|16@1+ (1,0) [0|65535] "mV"  PC
 SG_ S2P_Lmt1_Over_Ucell2_58 : 32|16@1+ (1,0) [0|65535] "mV"  PC
 SG_ S2P_Lmt1_Over_DUcell2_58 : 48|16@1+ (1,0) [0|65535] "mV"  PC

BO_ 2416569979 S2P_Lmt1__59: 8 SBMU
 SG_ S2P_Lmt1_Over_Ucell1_59 : 0|16@1+ (1,0) [0|65535] "mV"  PC
 SG_ S2P_Lmt1_Over_DUcell1_59 : 16|16@1+ (1,0) [0|65535] "mV"  PC
 SG_ S2P_Lmt1_Over_Ucell2_59 : 32|16@1+ (1,0) [0|65535] "mV"  PC
 SG_ S2P_Lmt1_Over_DUcell2_59 : 48|16@1+ (1,0) [0|65535] "mV"  PC

BO_ 2416569980 S2P_Lmt1__60: 8 SBMU
 SG_ S2P_Lmt1_Over_Ucell1_60 : 0|16@1+ (1,0) [0|65535] "mV"  PC
 SG_ S2P_Lmt1_Over_DUcell1_60 : 16|16@1+ (1,0) [0|65535] "mV"  PC
 SG_ S2P_Lmt1_Over_Ucell2_60 : 32|16@1+ (1,0) [0|65535] "mV"  PC
 SG_ S2P_Lmt1_Over_DUcell2_60 : 48|16@1+ (1,0) [0|65535] "mV"  PC

BO_ 2416569981 S2P_Lmt1__61: 8 SBMU
 SG_ S2P_Lmt1_Over_Ucell1_61 : 0|16@1+ (1,0) [0|65535] "mV"  PC
 SG_ S2P_Lmt1_Over_DUcell1_61 : 16|16@1+ (1,0) [0|65535] "mV"  PC
 SG_ S2P_Lmt1_Over_Ucell2_61 : 32|16@1+ (1,0) [0|65535] "mV"  PC
 SG_ S2P_Lmt1_Over_DUcell2_61 : 48|16@1+ (1,0) [0|65535] "mV"  PC

BO_ 2416569982 S2P_Lmt1__62: 8 SBMU
 SG_ S2P_Lmt1_Over_Ucell1_62 : 0|16@1+ (1,0) [0|65535] "mV"  PC
 SG_ S2P_Lmt1_Over_DUcell1_62 : 16|16@1+ (1,0) [0|65535] "mV"  PC
 SG_ S2P_Lmt1_Over_Ucell2_62 : 32|16@1+ (1,0) [0|65535] "mV"  PC
 SG_ S2P_Lmt1_Over_DUcell2_62 : 48|16@1+ (1,0) [0|65535] "mV"  PC

BO_ 2416569983 S2P_Lmt1__63: 8 SBMU
 SG_ S2P_Lmt1_Over_Ucell1_63 : 0|16@1+ (1,0) [0|65535] "mV"  PC
 SG_ S2P_Lmt1_Over_DUcell1_63 : 16|16@1+ (1,0) [0|65535] "mV"  PC
 SG_ S2P_Lmt1_Over_Ucell2_63 : 32|16@1+ (1,0) [0|65535] "mV"  PC
 SG_ S2P_Lmt1_Over_DUcell2_63 : 48|16@1+ (1,0) [0|65535] "mV"  PC

BO_ 2416635457 S2P_Lmt2__01: 8 SBMU
 SG_ S2P_Lmt2_Under_Ucell1_01 : 0|16@1+ (1,0) [0|65535] "mV"  PC
 SG_ S2P_Lmt2_Under_DUcell1_01 : 16|16@1+ (1,0) [0|65535] "mV"  PC
 SG_ S2P_Lmt2_Under_Ucell2_01 : 32|16@1+ (1,0) [0|65535] "mV"  PC
 SG_ S2P_Lmt2_Under_DUcell2_01 : 48|16@1+ (1,0) [0|65535] "mV"  PC

BO_ 2416635458 S2P_Lmt2__02: 8 SBMU
 SG_ S2P_Lmt2_Under_Ucell1_02 : 0|16@1+ (1,0) [0|65535] "mV"  PC
 SG_ S2P_Lmt2_Under_DUcell1_02 : 16|16@1+ (1,0) [0|65535] "mV"  PC
 SG_ S2P_Lmt2_Under_Ucell2_02 : 32|16@1+ (1,0) [0|65535] "mV"  PC
 SG_ S2P_Lmt2_Under_DUcell2_02 : 48|16@1+ (1,0) [0|65535] "mV"  PC

BO_ 2416635459 S2P_Lmt2__03: 8 SBMU
 SG_ S2P_Lmt2_Under_Ucell1_03 : 0|16@1+ (1,0) [0|65535] "mV"  PC
 SG_ S2P_Lmt2_Under_DUcell1_03 : 16|16@1+ (1,0) [0|65535] "mV"  PC
 SG_ S2P_Lmt2_Under_Ucell2_03 : 32|16@1+ (1,0) [0|65535] "mV"  PC
 SG_ S2P_Lmt2_Under_DUcell2_03 : 48|16@1+ (1,0) [0|65535] "mV"  PC

BO_ 2416635460 S2P_Lmt2__04: 8 SBMU
 SG_ S2P_Lmt2_Under_Ucell1_04 : 0|16@1+ (1,0) [0|65535] "mV"  PC
 SG_ S2P_Lmt2_Under_DUcell1_04 : 16|16@1+ (1,0) [0|65535] "mV"  PC
 SG_ S2P_Lmt2_Under_Ucell2_04 : 32|16@1+ (1,0) [0|65535] "mV"  PC
 SG_ S2P_Lmt2_Under_DUcell2_04 : 48|16@1+ (1,0) [0|65535] "mV"  PC

BO_ 2416635461 S2P_Lmt2__05: 8 SBMU
 SG_ S2P_Lmt2_Under_Ucell1_05 : 0|16@1+ (1,0) [0|65535] "mV"  PC
 SG_ S2P_Lmt2_Under_DUcell1_05 : 16|16@1+ (1,0) [0|65535] "mV"  PC
 SG_ S2P_Lmt2_Under_Ucell2_05 : 32|16@1+ (1,0) [0|65535] "mV"  PC
 SG_ S2P_Lmt2_Under_DUcell2_05 : 48|16@1+ (1,0) [0|65535] "mV"  PC

BO_ 2416635462 S2P_Lmt2__06: 8 SBMU
 SG_ S2P_Lmt2_Under_Ucell1_06 : 0|16@1+ (1,0) [0|65535] "mV"  PC
 SG_ S2P_Lmt2_Under_DUcell1_06 : 16|16@1+ (1,0) [0|65535] "mV"  PC
 SG_ S2P_Lmt2_Under_Ucell2_06 : 32|16@1+ (1,0) [0|65535] "mV"  PC
 SG_ S2P_Lmt2_Under_DUcell2_06 : 48|16@1+ (1,0) [0|65535] "mV"  PC

BO_ 2416635463 S2P_Lmt2__07: 8 SBMU
 SG_ S2P_Lmt2_Under_Ucell1_07 : 0|16@1+ (1,0) [0|65535] "mV"  PC
 SG_ S2P_Lmt2_Under_DUcell1_07 : 16|16@1+ (1,0) [0|65535] "mV"  PC
 SG_ S2P_Lmt2_Under_Ucell2_07 : 32|16@1+ (1,0) [0|65535] "mV"  PC
 SG_ S2P_Lmt2_Under_DUcell2_07 : 48|16@1+ (1,0) [0|65535] "mV"  PC

BO_ 2416635464 S2P_Lmt2__08: 8 SBMU
 SG_ S2P_Lmt2_Under_Ucell1_08 : 0|16@1+ (1,0) [0|65535] "mV"  PC
 SG_ S2P_Lmt2_Under_DUcell1_08 : 16|16@1+ (1,0) [0|65535] "mV"  PC
 SG_ S2P_Lmt2_Under_Ucell2_08 : 32|16@1+ (1,0) [0|65535] "mV"  PC
 SG_ S2P_Lmt2_Under_DUcell2_08 : 48|16@1+ (1,0) [0|65535] "mV"  PC

BO_ 2416635465 S2P_Lmt2__09: 8 SBMU
 SG_ S2P_Lmt2_Under_Ucell1_09 : 0|16@1+ (1,0) [0|65535] "mV"  PC
 SG_ S2P_Lmt2_Under_DUcell1_09 : 16|16@1+ (1,0) [0|65535] "mV"  PC
 SG_ S2P_Lmt2_Under_Ucell2_09 : 32|16@1+ (1,0) [0|65535] "mV"  PC
 SG_ S2P_Lmt2_Under_DUcell2_09 : 48|16@1+ (1,0) [0|65535] "mV"  PC

BO_ 2416635466 S2P_Lmt2__10: 8 SBMU
 SG_ S2P_Lmt2_Under_Ucell1_10 : 0|16@1+ (1,0) [0|65535] "mV"  PC
 SG_ S2P_Lmt2_Under_DUcell1_10 : 16|16@1+ (1,0) [0|65535] "mV"  PC
 SG_ S2P_Lmt2_Under_Ucell2_10 : 32|16@1+ (1,0) [0|65535] "mV"  PC
 SG_ S2P_Lmt2_Under_DUcell2_10 : 48|16@1+ (1,0) [0|65535] "mV"  PC

BO_ 2416635467 S2P_Lmt2__11: 8 SBMU
 SG_ S2P_Lmt2_Under_Ucell1_11 : 0|16@1+ (1,0) [0|65535] "mV"  PC
 SG_ S2P_Lmt2_Under_DUcell1_11 : 16|16@1+ (1,0) [0|65535] "mV"  PC
 SG_ S2P_Lmt2_Under_Ucell2_11 : 32|16@1+ (1,0) [0|65535] "mV"  PC
 SG_ S2P_Lmt2_Under_DUcell2_11 : 48|16@1+ (1,0) [0|65535] "mV"  PC

BO_ 2416635468 S2P_Lmt2__12: 8 SBMU
 SG_ S2P_Lmt2_Under_Ucell1_12 : 0|16@1+ (1,0) [0|65535] "mV"  PC
 SG_ S2P_Lmt2_Under_DUcell1_12 : 16|16@1+ (1,0) [0|65535] "mV"  PC
 SG_ S2P_Lmt2_Under_Ucell2_12 : 32|16@1+ (1,0) [0|65535] "mV"  PC
 SG_ S2P_Lmt2_Under_DUcell2_12 : 48|16@1+ (1,0) [0|65535] "mV"  PC

BO_ 2416635469 S2P_Lmt2__13: 8 SBMU
 SG_ S2P_Lmt2_Under_Ucell1_13 : 0|16@1+ (1,0) [0|65535] "mV"  PC
 SG_ S2P_Lmt2_Under_DUcell1_13 : 16|16@1+ (1,0) [0|65535] "mV"  PC
 SG_ S2P_Lmt2_Under_Ucell2_13 : 32|16@1+ (1,0) [0|65535] "mV"  PC
 SG_ S2P_Lmt2_Under_DUcell2_13 : 48|16@1+ (1,0) [0|65535] "mV"  PC

BO_ 2416635470 S2P_Lmt2__14: 8 SBMU
 SG_ S2P_Lmt2_Under_Ucell1_14 : 0|16@1+ (1,0) [0|65535] "mV"  PC
 SG_ S2P_Lmt2_Under_DUcell1_14 : 16|16@1+ (1,0) [0|65535] "mV"  PC
 SG_ S2P_Lmt2_Under_Ucell2_14 : 32|16@1+ (1,0) [0|65535] "mV"  PC
 SG_ S2P_Lmt2_Under_DUcell2_14 : 48|16@1+ (1,0) [0|65535] "mV"  PC

BO_ 2416635471 S2P_Lmt2__15: 8 SBMU
 SG_ S2P_Lmt2_Under_Ucell1_15 : 0|16@1+ (1,0) [0|65535] "mV"  PC
 SG_ S2P_Lmt2_Under_DUcell1_15 : 16|16@1+ (1,0) [0|65535] "mV"  PC
 SG_ S2P_Lmt2_Under_Ucell2_15 : 32|16@1+ (1,0) [0|65535] "mV"  PC
 SG_ S2P_Lmt2_Under_DUcell2_15 : 48|16@1+ (1,0) [0|65535] "mV"  PC

BO_ 2416635472 S2P_Lmt2__16: 8 SBMU
 SG_ S2P_Lmt2_Under_Ucell1_16 : 0|16@1+ (1,0) [0|65535] "mV"  PC
 SG_ S2P_Lmt2_Under_DUcell1_16 : 16|16@1+ (1,0) [0|65535] "mV"  PC
 SG_ S2P_Lmt2_Under_Ucell2_16 : 32|16@1+ (1,0) [0|65535] "mV"  PC
 SG_ S2P_Lmt2_Under_DUcell2_16 : 48|16@1+ (1,0) [0|65535] "mV"  PC

BO_ 2416635473 S2P_Lmt2__17: 8 SBMU
 SG_ S2P_Lmt2_Under_Ucell1_17 : 0|16@1+ (1,0) [0|65535] "mV"  PC
 SG_ S2P_Lmt2_Under_DUcell1_17 : 16|16@1+ (1,0) [0|65535] "mV"  PC
 SG_ S2P_Lmt2_Under_Ucell2_17 : 32|16@1+ (1,0) [0|65535] "mV"  PC
 SG_ S2P_Lmt2_Under_DUcell2_17 : 48|16@1+ (1,0) [0|65535] "mV"  PC

BO_ 2416635474 S2P_Lmt2__18: 8 SBMU
 SG_ S2P_Lmt2_Under_Ucell1_18 : 0|16@1+ (1,0) [0|65535] "mV"  PC
 SG_ S2P_Lmt2_Under_DUcell1_18 : 16|16@1+ (1,0) [0|65535] "mV"  PC
 SG_ S2P_Lmt2_Under_Ucell2_18 : 32|16@1+ (1,0) [0|65535] "mV"  PC
 SG_ S2P_Lmt2_Under_DUcell2_18 : 48|16@1+ (1,0) [0|65535] "mV"  PC

BO_ 2416635475 S2P_Lmt2__19: 8 SBMU
 SG_ S2P_Lmt2_Under_Ucell1_19 : 0|16@1+ (1,0) [0|65535] "mV"  PC
 SG_ S2P_Lmt2_Under_DUcell1_19 : 16|16@1+ (1,0) [0|65535] "mV"  PC
 SG_ S2P_Lmt2_Under_Ucell2_19 : 32|16@1+ (1,0) [0|65535] "mV"  PC
 SG_ S2P_Lmt2_Under_DUcell2_19 : 48|16@1+ (1,0) [0|65535] "mV"  PC

BO_ 2416635476 S2P_Lmt2__20: 8 SBMU
 SG_ S2P_Lmt2_Under_Ucell1_20 : 0|16@1+ (1,0) [0|65535] "mV"  PC
 SG_ S2P_Lmt2_Under_DUcell1_20 : 16|16@1+ (1,0) [0|65535] "mV"  PC
 SG_ S2P_Lmt2_Under_Ucell2_20 : 32|16@1+ (1,0) [0|65535] "mV"  PC
 SG_ S2P_Lmt2_Under_DUcell2_20 : 48|16@1+ (1,0) [0|65535] "mV"  PC

BO_ 2416635477 S2P_Lmt2__21: 8 SBMU
 SG_ S2P_Lmt2_Under_Ucell1_21 : 0|16@1+ (1,0) [0|65535] "mV"  PC
 SG_ S2P_Lmt2_Under_DUcell1_21 : 16|16@1+ (1,0) [0|65535] "mV"  PC
 SG_ S2P_Lmt2_Under_Ucell2_21 : 32|16@1+ (1,0) [0|65535] "mV"  PC
 SG_ S2P_Lmt2_Under_DUcell2_21 : 48|16@1+ (1,0) [0|65535] "mV"  PC

BO_ 2416635478 S2P_Lmt2__22: 8 SBMU
 SG_ S2P_Lmt2_Under_Ucell1_22 : 0|16@1+ (1,0) [0|65535] "mV"  PC
 SG_ S2P_Lmt2_Under_DUcell1_22 : 16|16@1+ (1,0) [0|65535] "mV"  PC
 SG_ S2P_Lmt2_Under_Ucell2_22 : 32|16@1+ (1,0) [0|65535] "mV"  PC
 SG_ S2P_Lmt2_Under_DUcell2_22 : 48|16@1+ (1,0) [0|65535] "mV"  PC

BO_ 2416635479 S2P_Lmt2__23: 8 SBMU
 SG_ S2P_Lmt2_Under_Ucell1_23 : 0|16@1+ (1,0) [0|65535] "mV"  PC
 SG_ S2P_Lmt2_Under_DUcell1_23 : 16|16@1+ (1,0) [0|65535] "mV"  PC
 SG_ S2P_Lmt2_Under_Ucell2_23 : 32|16@1+ (1,0) [0|65535] "mV"  PC
 SG_ S2P_Lmt2_Under_DUcell2_23 : 48|16@1+ (1,0) [0|65535] "mV"  PC

BO_ 2416635480 S2P_Lmt2__24: 8 SBMU
 SG_ S2P_Lmt2_Under_Ucell1_24 : 0|16@1+ (1,0) [0|65535] "mV"  PC
 SG_ S2P_Lmt2_Under_DUcell1_24 : 16|16@1+ (1,0) [0|65535] "mV"  PC
 SG_ S2P_Lmt2_Under_Ucell2_24 : 32|16@1+ (1,0) [0|65535] "mV"  PC
 SG_ S2P_Lmt2_Under_DUcell2_24 : 48|16@1+ (1,0) [0|65535] "mV"  PC

BO_ 2416635481 S2P_Lmt2__25: 8 SBMU
 SG_ S2P_Lmt2_Under_Ucell1_25 : 0|16@1+ (1,0) [0|65535] "mV"  PC
 SG_ S2P_Lmt2_Under_DUcell1_25 : 16|16@1+ (1,0) [0|65535] "mV"  PC
 SG_ S2P_Lmt2_Under_Ucell2_25 : 32|16@1+ (1,0) [0|65535] "mV"  PC
 SG_ S2P_Lmt2_Under_DUcell2_25 : 48|16@1+ (1,0) [0|65535] "mV"  PC

BO_ 2416635482 S2P_Lmt2__26: 8 SBMU
 SG_ S2P_Lmt2_Under_Ucell1_26 : 0|16@1+ (1,0) [0|65535] "mV"  PC
 SG_ S2P_Lmt2_Under_DUcell1_26 : 16|16@1+ (1,0) [0|65535] "mV"  PC
 SG_ S2P_Lmt2_Under_Ucell2_26 : 32|16@1+ (1,0) [0|65535] "mV"  PC
 SG_ S2P_Lmt2_Under_DUcell2_26 : 48|16@1+ (1,0) [0|65535] "mV"  PC

BO_ 2416635483 S2P_Lmt2__27: 8 SBMU
 SG_ S2P_Lmt2_Under_Ucell1_27 : 0|16@1+ (1,0) [0|65535] "mV"  PC
 SG_ S2P_Lmt2_Under_DUcell1_27 : 16|16@1+ (1,0) [0|65535] "mV"  PC
 SG_ S2P_Lmt2_Under_Ucell2_27 : 32|16@1+ (1,0) [0|65535] "mV"  PC
 SG_ S2P_Lmt2_Under_DUcell2_27 : 48|16@1+ (1,0) [0|65535] "mV"  PC

BO_ 2416635484 S2P_Lmt2__28: 8 SBMU
 SG_ S2P_Lmt2_Under_Ucell1_28 : 0|16@1+ (1,0) [0|65535] "mV"  PC
 SG_ S2P_Lmt2_Under_DUcell1_28 : 16|16@1+ (1,0) [0|65535] "mV"  PC
 SG_ S2P_Lmt2_Under_Ucell2_28 : 32|16@1+ (1,0) [0|65535] "mV"  PC
 SG_ S2P_Lmt2_Under_DUcell2_28 : 48|16@1+ (1,0) [0|65535] "mV"  PC

BO_ 2416635485 S2P_Lmt2__29: 8 SBMU
 SG_ S2P_Lmt2_Under_Ucell1_29 : 0|16@1+ (1,0) [0|65535] "mV"  PC
 SG_ S2P_Lmt2_Under_DUcell1_29 : 16|16@1+ (1,0) [0|65535] "mV"  PC
 SG_ S2P_Lmt2_Under_Ucell2_29 : 32|16@1+ (1,0) [0|65535] "mV"  PC
 SG_ S2P_Lmt2_Under_DUcell2_29 : 48|16@1+ (1,0) [0|65535] "mV"  PC

BO_ 2416635486 S2P_Lmt2__30: 8 SBMU
 SG_ S2P_Lmt2_Under_Ucell1_30 : 0|16@1+ (1,0) [0|65535] "mV"  PC
 SG_ S2P_Lmt2_Under_DUcell1_30 : 16|16@1+ (1,0) [0|65535] "mV"  PC
 SG_ S2P_Lmt2_Under_Ucell2_30 : 32|16@1+ (1,0) [0|65535] "mV"  PC
 SG_ S2P_Lmt2_Under_DUcell2_30 : 48|16@1+ (1,0) [0|65535] "mV"  PC

BO_ 2416635487 S2P_Lmt2__31: 8 SBMU
 SG_ S2P_Lmt2_Under_Ucell1_31 : 0|16@1+ (1,0) [0|65535] "mV"  PC
 SG_ S2P_Lmt2_Under_DUcell1_31 : 16|16@1+ (1,0) [0|65535] "mV"  PC
 SG_ S2P_Lmt2_Under_Ucell2_31 : 32|16@1+ (1,0) [0|65535] "mV"  PC
 SG_ S2P_Lmt2_Under_DUcell2_31 : 48|16@1+ (1,0) [0|65535] "mV"  PC

BO_ 2416635488 S2P_Lmt2__32: 8 SBMU
 SG_ S2P_Lmt2_Under_Ucell1_32 : 0|16@1+ (1,0) [0|65535] "mV"  PC
 SG_ S2P_Lmt2_Under_DUcell1_32 : 16|16@1+ (1,0) [0|65535] "mV"  PC
 SG_ S2P_Lmt2_Under_Ucell2_32 : 32|16@1+ (1,0) [0|65535] "mV"  PC
 SG_ S2P_Lmt2_Under_DUcell2_32 : 48|16@1+ (1,0) [0|65535] "mV"  PC

BO_ 2416635489 S2P_Lmt2__33: 8 SBMU
 SG_ S2P_Lmt2_Under_Ucell1_33 : 0|16@1+ (1,0) [0|65535] "mV"  PC
 SG_ S2P_Lmt2_Under_DUcell1_33 : 16|16@1+ (1,0) [0|65535] "mV"  PC
 SG_ S2P_Lmt2_Under_Ucell2_33 : 32|16@1+ (1,0) [0|65535] "mV"  PC
 SG_ S2P_Lmt2_Under_DUcell2_33 : 48|16@1+ (1,0) [0|65535] "mV"  PC

BO_ 2416635490 S2P_Lmt2__34: 8 SBMU
 SG_ S2P_Lmt2_Under_Ucell1_34 : 0|16@1+ (1,0) [0|65535] "mV"  PC
 SG_ S2P_Lmt2_Under_DUcell1_34 : 16|16@1+ (1,0) [0|65535] "mV"  PC
 SG_ S2P_Lmt2_Under_Ucell2_34 : 32|16@1+ (1,0) [0|65535] "mV"  PC
 SG_ S2P_Lmt2_Under_DUcell2_34 : 48|16@1+ (1,0) [0|65535] "mV"  PC

BO_ 2416635491 S2P_Lmt2__35: 8 SBMU
 SG_ S2P_Lmt2_Under_Ucell1_35 : 0|16@1+ (1,0) [0|65535] "mV"  PC
 SG_ S2P_Lmt2_Under_DUcell1_35 : 16|16@1+ (1,0) [0|65535] "mV"  PC
 SG_ S2P_Lmt2_Under_Ucell2_35 : 32|16@1+ (1,0) [0|65535] "mV"  PC
 SG_ S2P_Lmt2_Under_DUcell2_35 : 48|16@1+ (1,0) [0|65535] "mV"  PC

BO_ 2416635492 S2P_Lmt2__36: 8 SBMU
 SG_ S2P_Lmt2_Under_Ucell1_36 : 0|16@1+ (1,0) [0|65535] "mV"  PC
 SG_ S2P_Lmt2_Under_DUcell1_36 : 16|16@1+ (1,0) [0|65535] "mV"  PC
 SG_ S2P_Lmt2_Under_Ucell2_36 : 32|16@1+ (1,0) [0|65535] "mV"  PC
 SG_ S2P_Lmt2_Under_DUcell2_36 : 48|16@1+ (1,0) [0|65535] "mV"  PC

BO_ 2416635493 S2P_Lmt2__37: 8 SBMU
 SG_ S2P_Lmt2_Under_Ucell1_37 : 0|16@1+ (1,0) [0|65535] "mV"  PC
 SG_ S2P_Lmt2_Under_DUcell1_37 : 16|16@1+ (1,0) [0|65535] "mV"  PC
 SG_ S2P_Lmt2_Under_Ucell2_37 : 32|16@1+ (1,0) [0|65535] "mV"  PC
 SG_ S2P_Lmt2_Under_DUcell2_37 : 48|16@1+ (1,0) [0|65535] "mV"  PC

BO_ 2416635494 S2P_Lmt2__38: 8 SBMU
 SG_ S2P_Lmt2_Under_Ucell1_38 : 0|16@1+ (1,0) [0|65535] "mV"  PC
 SG_ S2P_Lmt2_Under_DUcell1_38 : 16|16@1+ (1,0) [0|65535] "mV"  PC
 SG_ S2P_Lmt2_Under_Ucell2_38 : 32|16@1+ (1,0) [0|65535] "mV"  PC
 SG_ S2P_Lmt2_Under_DUcell2_38 : 48|16@1+ (1,0) [0|65535] "mV"  PC

BO_ 2416635495 S2P_Lmt2__39: 8 SBMU
 SG_ S2P_Lmt2_Under_Ucell1_39 : 0|16@1+ (1,0) [0|65535] "mV"  PC
 SG_ S2P_Lmt2_Under_DUcell1_39 : 16|16@1+ (1,0) [0|65535] "mV"  PC
 SG_ S2P_Lmt2_Under_Ucell2_39 : 32|16@1+ (1,0) [0|65535] "mV"  PC
 SG_ S2P_Lmt2_Under_DUcell2_39 : 48|16@1+ (1,0) [0|65535] "mV"  PC

BO_ 2416635496 S2P_Lmt2__40: 8 SBMU
 SG_ S2P_Lmt2_Under_Ucell1_40 : 0|16@1+ (1,0) [0|65535] "mV"  PC
 SG_ S2P_Lmt2_Under_DUcell1_40 : 16|16@1+ (1,0) [0|65535] "mV"  PC
 SG_ S2P_Lmt2_Under_Ucell2_40 : 32|16@1+ (1,0) [0|65535] "mV"  PC
 SG_ S2P_Lmt2_Under_DUcell2_40 : 48|16@1+ (1,0) [0|65535] "mV"  PC

BO_ 2416635497 S2P_Lmt2__41: 8 SBMU
 SG_ S2P_Lmt2_Under_Ucell1_41 : 0|16@1+ (1,0) [0|65535] "mV"  PC
 SG_ S2P_Lmt2_Under_DUcell1_41 : 16|16@1+ (1,0) [0|65535] "mV"  PC
 SG_ S2P_Lmt2_Under_Ucell2_41 : 32|16@1+ (1,0) [0|65535] "mV"  PC
 SG_ S2P_Lmt2_Under_DUcell2_41 : 48|16@1+ (1,0) [0|65535] "mV"  PC

BO_ 2416635498 S2P_Lmt2__42: 8 SBMU
 SG_ S2P_Lmt2_Under_Ucell1_42 : 0|16@1+ (1,0) [0|65535] "mV"  PC
 SG_ S2P_Lmt2_Under_DUcell1_42 : 16|16@1+ (1,0) [0|65535] "mV"  PC
 SG_ S2P_Lmt2_Under_Ucell2_42 : 32|16@1+ (1,0) [0|65535] "mV"  PC
 SG_ S2P_Lmt2_Under_DUcell2_42 : 48|16@1+ (1,0) [0|65535] "mV"  PC

BO_ 2416635499 S2P_Lmt2__43: 8 SBMU
 SG_ S2P_Lmt2_Under_Ucell1_43 : 0|16@1+ (1,0) [0|65535] "mV"  PC
 SG_ S2P_Lmt2_Under_DUcell1_43 : 16|16@1+ (1,0) [0|65535] "mV"  PC
 SG_ S2P_Lmt2_Under_Ucell2_43 : 32|16@1+ (1,0) [0|65535] "mV"  PC
 SG_ S2P_Lmt2_Under_DUcell2_43 : 48|16@1+ (1,0) [0|65535] "mV"  PC

BO_ 2416635500 S2P_Lmt2__44: 8 SBMU
 SG_ S2P_Lmt2_Under_Ucell1_44 : 0|16@1+ (1,0) [0|65535] "mV"  PC
 SG_ S2P_Lmt2_Under_DUcell1_44 : 16|16@1+ (1,0) [0|65535] "mV"  PC
 SG_ S2P_Lmt2_Under_Ucell2_44 : 32|16@1+ (1,0) [0|65535] "mV"  PC
 SG_ S2P_Lmt2_Under_DUcell2_44 : 48|16@1+ (1,0) [0|65535] "mV"  PC

BO_ 2416635501 S2P_Lmt2__45: 8 SBMU
 SG_ S2P_Lmt2_Under_Ucell1_45 : 0|16@1+ (1,0) [0|65535] "mV"  PC
 SG_ S2P_Lmt2_Under_DUcell1_45 : 16|16@1+ (1,0) [0|65535] "mV"  PC
 SG_ S2P_Lmt2_Under_Ucell2_45 : 32|16@1+ (1,0) [0|65535] "mV"  PC
 SG_ S2P_Lmt2_Under_DUcell2_45 : 48|16@1+ (1,0) [0|65535] "mV"  PC

BO_ 2416635502 S2P_Lmt2__46: 8 SBMU
 SG_ S2P_Lmt2_Under_Ucell1_46 : 0|16@1+ (1,0) [0|65535] "mV"  PC
 SG_ S2P_Lmt2_Under_DUcell1_46 : 16|16@1+ (1,0) [0|65535] "mV"  PC
 SG_ S2P_Lmt2_Under_Ucell2_46 : 32|16@1+ (1,0) [0|65535] "mV"  PC
 SG_ S2P_Lmt2_Under_DUcell2_46 : 48|16@1+ (1,0) [0|65535] "mV"  PC

BO_ 2416635503 S2P_Lmt2__47: 8 SBMU
 SG_ S2P_Lmt2_Under_Ucell1_47 : 0|16@1+ (1,0) [0|65535] "mV"  PC
 SG_ S2P_Lmt2_Under_DUcell1_47 : 16|16@1+ (1,0) [0|65535] "mV"  PC
 SG_ S2P_Lmt2_Under_Ucell2_47 : 32|16@1+ (1,0) [0|65535] "mV"  PC
 SG_ S2P_Lmt2_Under_DUcell2_47 : 48|16@1+ (1,0) [0|65535] "mV"  PC

BO_ 2416635504 S2P_Lmt2__48: 8 SBMU
 SG_ S2P_Lmt2_Under_Ucell1_48 : 0|16@1+ (1,0) [0|65535] "mV"  PC
 SG_ S2P_Lmt2_Under_DUcell1_48 : 16|16@1+ (1,0) [0|65535] "mV"  PC
 SG_ S2P_Lmt2_Under_Ucell2_48 : 32|16@1+ (1,0) [0|65535] "mV"  PC
 SG_ S2P_Lmt2_Under_DUcell2_48 : 48|16@1+ (1,0) [0|65535] "mV"  PC

BO_ 2416635505 S2P_Lmt2__49: 8 SBMU
 SG_ S2P_Lmt2_Under_Ucell1_49 : 0|16@1+ (1,0) [0|65535] "mV"  PC
 SG_ S2P_Lmt2_Under_DUcell1_49 : 16|16@1+ (1,0) [0|65535] "mV"  PC
 SG_ S2P_Lmt2_Under_Ucell2_49 : 32|16@1+ (1,0) [0|65535] "mV"  PC
 SG_ S2P_Lmt2_Under_DUcell2_49 : 48|16@1+ (1,0) [0|65535] "mV"  PC

BO_ 2416635506 S2P_Lmt2__50: 8 SBMU
 SG_ S2P_Lmt2_Under_Ucell1_50 : 0|16@1+ (1,0) [0|65535] "mV"  PC
 SG_ S2P_Lmt2_Under_DUcell1_50 : 16|16@1+ (1,0) [0|65535] "mV"  PC
 SG_ S2P_Lmt2_Under_Ucell2_50 : 32|16@1+ (1,0) [0|65535] "mV"  PC
 SG_ S2P_Lmt2_Under_DUcell2_50 : 48|16@1+ (1,0) [0|65535] "mV"  PC

BO_ 2416635507 S2P_Lmt2__51: 8 SBMU
 SG_ S2P_Lmt2_Under_Ucell1_51 : 0|16@1+ (1,0) [0|65535] "mV"  PC
 SG_ S2P_Lmt2_Under_DUcell1_51 : 16|16@1+ (1,0) [0|65535] "mV"  PC
 SG_ S2P_Lmt2_Under_Ucell2_51 : 32|16@1+ (1,0) [0|65535] "mV"  PC
 SG_ S2P_Lmt2_Under_DUcell2_51 : 48|16@1+ (1,0) [0|65535] "mV"  PC

BO_ 2416635508 S2P_Lmt2__52: 8 SBMU
 SG_ S2P_Lmt2_Under_Ucell1_52 : 0|16@1+ (1,0) [0|65535] "mV"  PC
 SG_ S2P_Lmt2_Under_DUcell1_52 : 16|16@1+ (1,0) [0|65535] "mV"  PC
 SG_ S2P_Lmt2_Under_Ucell2_52 : 32|16@1+ (1,0) [0|65535] "mV"  PC
 SG_ S2P_Lmt2_Under_DUcell2_52 : 48|16@1+ (1,0) [0|65535] "mV"  PC

BO_ 2416635509 S2P_Lmt2__53: 8 SBMU
 SG_ S2P_Lmt2_Under_Ucell1_53 : 0|16@1+ (1,0) [0|65535] "mV"  PC
 SG_ S2P_Lmt2_Under_DUcell1_53 : 16|16@1+ (1,0) [0|65535] "mV"  PC
 SG_ S2P_Lmt2_Under_Ucell2_53 : 32|16@1+ (1,0) [0|65535] "mV"  PC
 SG_ S2P_Lmt2_Under_DUcell2_53 : 48|16@1+ (1,0) [0|65535] "mV"  PC

BO_ 2416635510 S2P_Lmt2__54: 8 SBMU
 SG_ S2P_Lmt2_Under_Ucell1_54 : 0|16@1+ (1,0) [0|65535] "mV"  PC
 SG_ S2P_Lmt2_Under_DUcell1_54 : 16|16@1+ (1,0) [0|65535] "mV"  PC
 SG_ S2P_Lmt2_Under_Ucell2_54 : 32|16@1+ (1,0) [0|65535] "mV"  PC
 SG_ S2P_Lmt2_Under_DUcell2_54 : 48|16@1+ (1,0) [0|65535] "mV"  PC

BO_ 2416635511 S2P_Lmt2__55: 8 SBMU
 SG_ S2P_Lmt2_Under_Ucell1_55 : 0|16@1+ (1,0) [0|65535] "mV"  PC
 SG_ S2P_Lmt2_Under_DUcell1_55 : 16|16@1+ (1,0) [0|65535] "mV"  PC
 SG_ S2P_Lmt2_Under_Ucell2_55 : 32|16@1+ (1,0) [0|65535] "mV"  PC
 SG_ S2P_Lmt2_Under_DUcell2_55 : 48|16@1+ (1,0) [0|65535] "mV"  PC

BO_ 2416635512 S2P_Lmt2__56: 8 SBMU
 SG_ S2P_Lmt2_Under_Ucell1_56 : 0|16@1+ (1,0) [0|65535] "mV"  PC
 SG_ S2P_Lmt2_Under_DUcell1_56 : 16|16@1+ (1,0) [0|65535] "mV"  PC
 SG_ S2P_Lmt2_Under_Ucell2_56 : 32|16@1+ (1,0) [0|65535] "mV"  PC
 SG_ S2P_Lmt2_Under_DUcell2_56 : 48|16@1+ (1,0) [0|65535] "mV"  PC

BO_ 2416635513 S2P_Lmt2__57: 8 SBMU
 SG_ S2P_Lmt2_Under_Ucell1_57 : 0|16@1+ (1,0) [0|65535] "mV"  PC
 SG_ S2P_Lmt2_Under_DUcell1_57 : 16|16@1+ (1,0) [0|65535] "mV"  PC
 SG_ S2P_Lmt2_Under_Ucell2_57 : 32|16@1+ (1,0) [0|65535] "mV"  PC
 SG_ S2P_Lmt2_Under_DUcell2_57 : 48|16@1+ (1,0) [0|65535] "mV"  PC

BO_ 2416635514 S2P_Lmt2__58: 8 SBMU
 SG_ S2P_Lmt2_Under_Ucell1_58 : 0|16@1+ (1,0) [0|65535] "mV"  PC
 SG_ S2P_Lmt2_Under_DUcell1_58 : 16|16@1+ (1,0) [0|65535] "mV"  PC
 SG_ S2P_Lmt2_Under_Ucell2_58 : 32|16@1+ (1,0) [0|65535] "mV"  PC
 SG_ S2P_Lmt2_Under_DUcell2_58 : 48|16@1+ (1,0) [0|65535] "mV"  PC

BO_ 2416635515 S2P_Lmt2__59: 8 SBMU
 SG_ S2P_Lmt2_Under_Ucell1_59 : 0|16@1+ (1,0) [0|65535] "mV"  PC
 SG_ S2P_Lmt2_Under_DUcell1_59 : 16|16@1+ (1,0) [0|65535] "mV"  PC
 SG_ S2P_Lmt2_Under_Ucell2_59 : 32|16@1+ (1,0) [0|65535] "mV"  PC
 SG_ S2P_Lmt2_Under_DUcell2_59 : 48|16@1+ (1,0) [0|65535] "mV"  PC

BO_ 2416635516 S2P_Lmt2__60: 8 SBMU
 SG_ S2P_Lmt2_Under_Ucell1_60 : 0|16@1+ (1,0) [0|65535] "mV"  PC
 SG_ S2P_Lmt2_Under_DUcell1_60 : 16|16@1+ (1,0) [0|65535] "mV"  PC
 SG_ S2P_Lmt2_Under_Ucell2_60 : 32|16@1+ (1,0) [0|65535] "mV"  PC
 SG_ S2P_Lmt2_Under_DUcell2_60 : 48|16@1+ (1,0) [0|65535] "mV"  PC

BO_ 2416635517 S2P_Lmt2__61: 8 SBMU
 SG_ S2P_Lmt2_Under_Ucell1_61 : 0|16@1+ (1,0) [0|65535] "mV"  PC
 SG_ S2P_Lmt2_Under_DUcell1_61 : 16|16@1+ (1,0) [0|65535] "mV"  PC
 SG_ S2P_Lmt2_Under_Ucell2_61 : 32|16@1+ (1,0) [0|65535] "mV"  PC
 SG_ S2P_Lmt2_Under_DUcell2_61 : 48|16@1+ (1,0) [0|65535] "mV"  PC

BO_ 2416635518 S2P_Lmt2__62: 8 SBMU
 SG_ S2P_Lmt2_Under_Ucell1_62 : 0|16@1+ (1,0) [0|65535] "mV"  PC
 SG_ S2P_Lmt2_Under_DUcell1_62 : 16|16@1+ (1,0) [0|65535] "mV"  PC
 SG_ S2P_Lmt2_Under_Ucell2_62 : 32|16@1+ (1,0) [0|65535] "mV"  PC
 SG_ S2P_Lmt2_Under_DUcell2_62 : 48|16@1+ (1,0) [0|65535] "mV"  PC

BO_ 2416635519 S2P_Lmt2__63: 8 SBMU
 SG_ S2P_Lmt2_Under_Ucell1_63 : 0|16@1+ (1,0) [0|65535] "mV"  PC
 SG_ S2P_Lmt2_Under_DUcell1_63 : 16|16@1+ (1,0) [0|65535] "mV"  PC
 SG_ S2P_Lmt2_Under_Ucell2_63 : 32|16@1+ (1,0) [0|65535] "mV"  PC
 SG_ S2P_Lmt2_Under_DUcell2_63 : 48|16@1+ (1,0) [0|65535] "mV"  PC

BO_ 2416700993 S2P_Lmt3__01: 8 SBMU
 SG_ S2P_Lmt3_Over_Ucell3_01 : 0|16@1+ (1,0) [0|65535] "mV"  PC
 SG_ S2P_Lmt3_Over_DUcell3_01 : 16|16@1+ (1,0) [0|65535] "mV"  PC
 SG_ S2P_Lmt3_Under_Ucell3_01 : 32|16@1+ (1,0) [0|65535] "mV"  PC
 SG_ S2P_Lmt3_Under_DUcell3_01 : 48|16@1+ (1,0) [0|65535] "mV"  PC

BO_ 2416700994 S2P_Lmt3__02: 8 SBMU
 SG_ S2P_Lmt3_Over_Ucell3_02 : 0|16@1+ (1,0) [0|65535] "mV"  PC
 SG_ S2P_Lmt3_Over_DUcell3_02 : 16|16@1+ (1,0) [0|65535] "mV"  PC
 SG_ S2P_Lmt3_Under_Ucell3_02 : 32|16@1+ (1,0) [0|65535] "mV"  PC
 SG_ S2P_Lmt3_Under_DUcell3_02 : 48|16@1+ (1,0) [0|65535] "mV"  PC

BO_ 2416700995 S2P_Lmt3__03: 8 SBMU
 SG_ S2P_Lmt3_Over_Ucell3_03 : 0|16@1+ (1,0) [0|65535] "mV"  PC
 SG_ S2P_Lmt3_Over_DUcell3_03 : 16|16@1+ (1,0) [0|65535] "mV"  PC
 SG_ S2P_Lmt3_Under_Ucell3_03 : 32|16@1+ (1,0) [0|65535] "mV"  PC
 SG_ S2P_Lmt3_Under_DUcell3_03 : 48|16@1+ (1,0) [0|65535] "mV"  PC

BO_ 2416700996 S2P_Lmt3__04: 8 SBMU
 SG_ S2P_Lmt3_Over_Ucell3_04 : 0|16@1+ (1,0) [0|65535] "mV"  PC
 SG_ S2P_Lmt3_Over_DUcell3_04 : 16|16@1+ (1,0) [0|65535] "mV"  PC
 SG_ S2P_Lmt3_Under_Ucell3_04 : 32|16@1+ (1,0) [0|65535] "mV"  PC
 SG_ S2P_Lmt3_Under_DUcell3_04 : 48|16@1+ (1,0) [0|65535] "mV"  PC

BO_ 2416700997 S2P_Lmt3__05: 8 SBMU
 SG_ S2P_Lmt3_Over_Ucell3_05 : 0|16@1+ (1,0) [0|65535] "mV"  PC
 SG_ S2P_Lmt3_Over_DUcell3_05 : 16|16@1+ (1,0) [0|65535] "mV"  PC
 SG_ S2P_Lmt3_Under_Ucell3_05 : 32|16@1+ (1,0) [0|65535] "mV"  PC
 SG_ S2P_Lmt3_Under_DUcell3_05 : 48|16@1+ (1,0) [0|65535] "mV"  PC

BO_ 2416700998 S2P_Lmt3__06: 8 SBMU
 SG_ S2P_Lmt3_Over_Ucell3_06 : 0|16@1+ (1,0) [0|65535] "mV"  PC
 SG_ S2P_Lmt3_Over_DUcell3_06 : 16|16@1+ (1,0) [0|65535] "mV"  PC
 SG_ S2P_Lmt3_Under_Ucell3_06 : 32|16@1+ (1,0) [0|65535] "mV"  PC
 SG_ S2P_Lmt3_Under_DUcell3_06 : 48|16@1+ (1,0) [0|65535] "mV"  PC

BO_ 2416700999 S2P_Lmt3__07: 8 SBMU
 SG_ S2P_Lmt3_Over_Ucell3_07 : 0|16@1+ (1,0) [0|65535] "mV"  PC
 SG_ S2P_Lmt3_Over_DUcell3_07 : 16|16@1+ (1,0) [0|65535] "mV"  PC
 SG_ S2P_Lmt3_Under_Ucell3_07 : 32|16@1+ (1,0) [0|65535] "mV"  PC
 SG_ S2P_Lmt3_Under_DUcell3_07 : 48|16@1+ (1,0) [0|65535] "mV"  PC

BO_ 2416701000 S2P_Lmt3__08: 8 SBMU
 SG_ S2P_Lmt3_Over_Ucell3_08 : 0|16@1+ (1,0) [0|65535] "mV"  PC
 SG_ S2P_Lmt3_Over_DUcell3_08 : 16|16@1+ (1,0) [0|65535] "mV"  PC
 SG_ S2P_Lmt3_Under_Ucell3_08 : 32|16@1+ (1,0) [0|65535] "mV"  PC
 SG_ S2P_Lmt3_Under_DUcell3_08 : 48|16@1+ (1,0) [0|65535] "mV"  PC

BO_ 2416701001 S2P_Lmt3__09: 8 SBMU
 SG_ S2P_Lmt3_Over_Ucell3_09 : 0|16@1+ (1,0) [0|65535] "mV"  PC
 SG_ S2P_Lmt3_Over_DUcell3_09 : 16|16@1+ (1,0) [0|65535] "mV"  PC
 SG_ S2P_Lmt3_Under_Ucell3_09 : 32|16@1+ (1,0) [0|65535] "mV"  PC
 SG_ S2P_Lmt3_Under_DUcell3_09 : 48|16@1+ (1,0) [0|65535] "mV"  PC

BO_ 2416701002 S2P_Lmt3__10: 8 SBMU
 SG_ S2P_Lmt3_Over_Ucell3_10 : 0|16@1+ (1,0) [0|65535] "mV"  PC
 SG_ S2P_Lmt3_Over_DUcell3_10 : 16|16@1+ (1,0) [0|65535] "mV"  PC
 SG_ S2P_Lmt3_Under_Ucell3_10 : 32|16@1+ (1,0) [0|65535] "mV"  PC
 SG_ S2P_Lmt3_Under_DUcell3_10 : 48|16@1+ (1,0) [0|65535] "mV"  PC

BO_ 2416701003 S2P_Lmt3__11: 8 SBMU
 SG_ S2P_Lmt3_Over_Ucell3_11 : 0|16@1+ (1,0) [0|65535] "mV"  PC
 SG_ S2P_Lmt3_Over_DUcell3_11 : 16|16@1+ (1,0) [0|65535] "mV"  PC
 SG_ S2P_Lmt3_Under_Ucell3_11 : 32|16@1+ (1,0) [0|65535] "mV"  PC
 SG_ S2P_Lmt3_Under_DUcell3_11 : 48|16@1+ (1,0) [0|65535] "mV"  PC

BO_ 2416701004 S2P_Lmt3__12: 8 SBMU
 SG_ S2P_Lmt3_Over_Ucell3_12 : 0|16@1+ (1,0) [0|65535] "mV"  PC
 SG_ S2P_Lmt3_Over_DUcell3_12 : 16|16@1+ (1,0) [0|65535] "mV"  PC
 SG_ S2P_Lmt3_Under_Ucell3_12 : 32|16@1+ (1,0) [0|65535] "mV"  PC
 SG_ S2P_Lmt3_Under_DUcell3_12 : 48|16@1+ (1,0) [0|65535] "mV"  PC

BO_ 2416701005 S2P_Lmt3__13: 8 SBMU
 SG_ S2P_Lmt3_Over_Ucell3_13 : 0|16@1+ (1,0) [0|65535] "mV"  PC
 SG_ S2P_Lmt3_Over_DUcell3_13 : 16|16@1+ (1,0) [0|65535] "mV"  PC
 SG_ S2P_Lmt3_Under_Ucell3_13 : 32|16@1+ (1,0) [0|65535] "mV"  PC
 SG_ S2P_Lmt3_Under_DUcell3_13 : 48|16@1+ (1,0) [0|65535] "mV"  PC

BO_ 2416701006 S2P_Lmt3__14: 8 SBMU
 SG_ S2P_Lmt3_Over_Ucell3_14 : 0|16@1+ (1,0) [0|65535] "mV"  PC
 SG_ S2P_Lmt3_Over_DUcell3_14 : 16|16@1+ (1,0) [0|65535] "mV"  PC
 SG_ S2P_Lmt3_Under_Ucell3_14 : 32|16@1+ (1,0) [0|65535] "mV"  PC
 SG_ S2P_Lmt3_Under_DUcell3_14 : 48|16@1+ (1,0) [0|65535] "mV"  PC

BO_ 2416701007 S2P_Lmt3__15: 8 SBMU
 SG_ S2P_Lmt3_Over_Ucell3_15 : 0|16@1+ (1,0) [0|65535] "mV"  PC
 SG_ S2P_Lmt3_Over_DUcell3_15 : 16|16@1+ (1,0) [0|65535] "mV"  PC
 SG_ S2P_Lmt3_Under_Ucell3_15 : 32|16@1+ (1,0) [0|65535] "mV"  PC
 SG_ S2P_Lmt3_Under_DUcell3_15 : 48|16@1+ (1,0) [0|65535] "mV"  PC

BO_ 2416701008 S2P_Lmt3__16: 8 SBMU
 SG_ S2P_Lmt3_Over_Ucell3_16 : 0|16@1+ (1,0) [0|65535] "mV"  PC
 SG_ S2P_Lmt3_Over_DUcell3_16 : 16|16@1+ (1,0) [0|65535] "mV"  PC
 SG_ S2P_Lmt3_Under_Ucell3_16 : 32|16@1+ (1,0) [0|65535] "mV"  PC
 SG_ S2P_Lmt3_Under_DUcell3_16 : 48|16@1+ (1,0) [0|65535] "mV"  PC

BO_ 2416701009 S2P_Lmt3__17: 8 SBMU
 SG_ S2P_Lmt3_Over_Ucell3_17 : 0|16@1+ (1,0) [0|65535] "mV"  PC
 SG_ S2P_Lmt3_Over_DUcell3_17 : 16|16@1+ (1,0) [0|65535] "mV"  PC
 SG_ S2P_Lmt3_Under_Ucell3_17 : 32|16@1+ (1,0) [0|65535] "mV"  PC
 SG_ S2P_Lmt3_Under_DUcell3_17 : 48|16@1+ (1,0) [0|65535] "mV"  PC

BO_ 2416701010 S2P_Lmt3__18: 8 SBMU
 SG_ S2P_Lmt3_Over_Ucell3_18 : 0|16@1+ (1,0) [0|65535] "mV"  PC
 SG_ S2P_Lmt3_Over_DUcell3_18 : 16|16@1+ (1,0) [0|65535] "mV"  PC
 SG_ S2P_Lmt3_Under_Ucell3_18 : 32|16@1+ (1,0) [0|65535] "mV"  PC
 SG_ S2P_Lmt3_Under_DUcell3_18 : 48|16@1+ (1,0) [0|65535] "mV"  PC

BO_ 2416701011 S2P_Lmt3__19: 8 SBMU
 SG_ S2P_Lmt3_Over_Ucell3_19 : 0|16@1+ (1,0) [0|65535] "mV"  PC
 SG_ S2P_Lmt3_Over_DUcell3_19 : 16|16@1+ (1,0) [0|65535] "mV"  PC
 SG_ S2P_Lmt3_Under_Ucell3_19 : 32|16@1+ (1,0) [0|65535] "mV"  PC
 SG_ S2P_Lmt3_Under_DUcell3_19 : 48|16@1+ (1,0) [0|65535] "mV"  PC

BO_ 2416701012 S2P_Lmt3__20: 8 SBMU
 SG_ S2P_Lmt3_Over_Ucell3_20 : 0|16@1+ (1,0) [0|65535] "mV"  PC
 SG_ S2P_Lmt3_Over_DUcell3_20 : 16|16@1+ (1,0) [0|65535] "mV"  PC
 SG_ S2P_Lmt3_Under_Ucell3_20 : 32|16@1+ (1,0) [0|65535] "mV"  PC
 SG_ S2P_Lmt3_Under_DUcell3_20 : 48|16@1+ (1,0) [0|65535] "mV"  PC

BO_ 2416701013 S2P_Lmt3__21: 8 SBMU
 SG_ S2P_Lmt3_Over_Ucell3_21 : 0|16@1+ (1,0) [0|65535] "mV"  PC
 SG_ S2P_Lmt3_Over_DUcell3_21 : 16|16@1+ (1,0) [0|65535] "mV"  PC
 SG_ S2P_Lmt3_Under_Ucell3_21 : 32|16@1+ (1,0) [0|65535] "mV"  PC
 SG_ S2P_Lmt3_Under_DUcell3_21 : 48|16@1+ (1,0) [0|65535] "mV"  PC

BO_ 2416701014 S2P_Lmt3__22: 8 SBMU
 SG_ S2P_Lmt3_Over_Ucell3_22 : 0|16@1+ (1,0) [0|65535] "mV"  PC
 SG_ S2P_Lmt3_Over_DUcell3_22 : 16|16@1+ (1,0) [0|65535] "mV"  PC
 SG_ S2P_Lmt3_Under_Ucell3_22 : 32|16@1+ (1,0) [0|65535] "mV"  PC
 SG_ S2P_Lmt3_Under_DUcell3_22 : 48|16@1+ (1,0) [0|65535] "mV"  PC

BO_ 2416701015 S2P_Lmt3__23: 8 SBMU
 SG_ S2P_Lmt3_Over_Ucell3_23 : 0|16@1+ (1,0) [0|65535] "mV"  PC
 SG_ S2P_Lmt3_Over_DUcell3_23 : 16|16@1+ (1,0) [0|65535] "mV"  PC
 SG_ S2P_Lmt3_Under_Ucell3_23 : 32|16@1+ (1,0) [0|65535] "mV"  PC
 SG_ S2P_Lmt3_Under_DUcell3_23 : 48|16@1+ (1,0) [0|65535] "mV"  PC

BO_ 2416701016 S2P_Lmt3__24: 8 SBMU
 SG_ S2P_Lmt3_Over_Ucell3_24 : 0|16@1+ (1,0) [0|65535] "mV"  PC
 SG_ S2P_Lmt3_Over_DUcell3_24 : 16|16@1+ (1,0) [0|65535] "mV"  PC
 SG_ S2P_Lmt3_Under_Ucell3_24 : 32|16@1+ (1,0) [0|65535] "mV"  PC
 SG_ S2P_Lmt3_Under_DUcell3_24 : 48|16@1+ (1,0) [0|65535] "mV"  PC

BO_ 2416701017 S2P_Lmt3__25: 8 SBMU
 SG_ S2P_Lmt3_Over_Ucell3_25 : 0|16@1+ (1,0) [0|65535] "mV"  PC
 SG_ S2P_Lmt3_Over_DUcell3_25 : 16|16@1+ (1,0) [0|65535] "mV"  PC
 SG_ S2P_Lmt3_Under_Ucell3_25 : 32|16@1+ (1,0) [0|65535] "mV"  PC
 SG_ S2P_Lmt3_Under_DUcell3_25 : 48|16@1+ (1,0) [0|65535] "mV"  PC

BO_ 2416701018 S2P_Lmt3__26: 8 SBMU
 SG_ S2P_Lmt3_Over_Ucell3_26 : 0|16@1+ (1,0) [0|65535] "mV"  PC
 SG_ S2P_Lmt3_Over_DUcell3_26 : 16|16@1+ (1,0) [0|65535] "mV"  PC
 SG_ S2P_Lmt3_Under_Ucell3_26 : 32|16@1+ (1,0) [0|65535] "mV"  PC
 SG_ S2P_Lmt3_Under_DUcell3_26 : 48|16@1+ (1,0) [0|65535] "mV"  PC

BO_ 2416701019 S2P_Lmt3__27: 8 SBMU
 SG_ S2P_Lmt3_Over_Ucell3_27 : 0|16@1+ (1,0) [0|65535] "mV"  PC
 SG_ S2P_Lmt3_Over_DUcell3_27 : 16|16@1+ (1,0) [0|65535] "mV"  PC
 SG_ S2P_Lmt3_Under_Ucell3_27 : 32|16@1+ (1,0) [0|65535] "mV"  PC
 SG_ S2P_Lmt3_Under_DUcell3_27 : 48|16@1+ (1,0) [0|65535] "mV"  PC

BO_ 2416701020 S2P_Lmt3__28: 8 SBMU
 SG_ S2P_Lmt3_Over_Ucell3_28 : 0|16@1+ (1,0) [0|65535] "mV"  PC
 SG_ S2P_Lmt3_Over_DUcell3_28 : 16|16@1+ (1,0) [0|65535] "mV"  PC
 SG_ S2P_Lmt3_Under_Ucell3_28 : 32|16@1+ (1,0) [0|65535] "mV"  PC
 SG_ S2P_Lmt3_Under_DUcell3_28 : 48|16@1+ (1,0) [0|65535] "mV"  PC

BO_ 2416701021 S2P_Lmt3__29: 8 SBMU
 SG_ S2P_Lmt3_Over_Ucell3_29 : 0|16@1+ (1,0) [0|65535] "mV"  PC
 SG_ S2P_Lmt3_Over_DUcell3_29 : 16|16@1+ (1,0) [0|65535] "mV"  PC
 SG_ S2P_Lmt3_Under_Ucell3_29 : 32|16@1+ (1,0) [0|65535] "mV"  PC
 SG_ S2P_Lmt3_Under_DUcell3_29 : 48|16@1+ (1,0) [0|65535] "mV"  PC

BO_ 2416701022 S2P_Lmt3__30: 8 SBMU
 SG_ S2P_Lmt3_Over_Ucell3_30 : 0|16@1+ (1,0) [0|65535] "mV"  PC
 SG_ S2P_Lmt3_Over_DUcell3_30 : 16|16@1+ (1,0) [0|65535] "mV"  PC
 SG_ S2P_Lmt3_Under_Ucell3_30 : 32|16@1+ (1,0) [0|65535] "mV"  PC
 SG_ S2P_Lmt3_Under_DUcell3_30 : 48|16@1+ (1,0) [0|65535] "mV"  PC

BO_ 2416701023 S2P_Lmt3__31: 8 SBMU
 SG_ S2P_Lmt3_Over_Ucell3_31 : 0|16@1+ (1,0) [0|65535] "mV"  PC
 SG_ S2P_Lmt3_Over_DUcell3_31 : 16|16@1+ (1,0) [0|65535] "mV"  PC
 SG_ S2P_Lmt3_Under_Ucell3_31 : 32|16@1+ (1,0) [0|65535] "mV"  PC
 SG_ S2P_Lmt3_Under_DUcell3_31 : 48|16@1+ (1,0) [0|65535] "mV"  PC

BO_ 2416701024 S2P_Lmt3__32: 8 SBMU
 SG_ S2P_Lmt3_Over_Ucell3_32 : 0|16@1+ (1,0) [0|65535] "mV"  PC
 SG_ S2P_Lmt3_Over_DUcell3_32 : 16|16@1+ (1,0) [0|65535] "mV"  PC
 SG_ S2P_Lmt3_Under_Ucell3_32 : 32|16@1+ (1,0) [0|65535] "mV"  PC
 SG_ S2P_Lmt3_Under_DUcell3_32 : 48|16@1+ (1,0) [0|65535] "mV"  PC

BO_ 2416701025 S2P_Lmt3__33: 8 SBMU
 SG_ S2P_Lmt3_Over_Ucell3_33 : 0|16@1+ (1,0) [0|65535] "mV"  PC
 SG_ S2P_Lmt3_Over_DUcell3_33 : 16|16@1+ (1,0) [0|65535] "mV"  PC
 SG_ S2P_Lmt3_Under_Ucell3_33 : 32|16@1+ (1,0) [0|65535] "mV"  PC
 SG_ S2P_Lmt3_Under_DUcell3_33 : 48|16@1+ (1,0) [0|65535] "mV"  PC

BO_ 2416701026 S2P_Lmt3__34: 8 SBMU
 SG_ S2P_Lmt3_Over_Ucell3_34 : 0|16@1+ (1,0) [0|65535] "mV"  PC
 SG_ S2P_Lmt3_Over_DUcell3_34 : 16|16@1+ (1,0) [0|65535] "mV"  PC
 SG_ S2P_Lmt3_Under_Ucell3_34 : 32|16@1+ (1,0) [0|65535] "mV"  PC
 SG_ S2P_Lmt3_Under_DUcell3_34 : 48|16@1+ (1,0) [0|65535] "mV"  PC

BO_ 2416701027 S2P_Lmt3__35: 8 SBMU
 SG_ S2P_Lmt3_Over_Ucell3_35 : 0|16@1+ (1,0) [0|65535] "mV"  PC
 SG_ S2P_Lmt3_Over_DUcell3_35 : 16|16@1+ (1,0) [0|65535] "mV"  PC
 SG_ S2P_Lmt3_Under_Ucell3_35 : 32|16@1+ (1,0) [0|65535] "mV"  PC
 SG_ S2P_Lmt3_Under_DUcell3_35 : 48|16@1+ (1,0) [0|65535] "mV"  PC

BO_ 2416701028 S2P_Lmt3__36: 8 SBMU
 SG_ S2P_Lmt3_Over_Ucell3_36 : 0|16@1+ (1,0) [0|65535] "mV"  PC
 SG_ S2P_Lmt3_Over_DUcell3_36 : 16|16@1+ (1,0) [0|65535] "mV"  PC
 SG_ S2P_Lmt3_Under_Ucell3_36 : 32|16@1+ (1,0) [0|65535] "mV"  PC
 SG_ S2P_Lmt3_Under_DUcell3_36 : 48|16@1+ (1,0) [0|65535] "mV"  PC

BO_ 2416701029 S2P_Lmt3__37: 8 SBMU
 SG_ S2P_Lmt3_Over_Ucell3_37 : 0|16@1+ (1,0) [0|65535] "mV"  PC
 SG_ S2P_Lmt3_Over_DUcell3_37 : 16|16@1+ (1,0) [0|65535] "mV"  PC
 SG_ S2P_Lmt3_Under_Ucell3_37 : 32|16@1+ (1,0) [0|65535] "mV"  PC
 SG_ S2P_Lmt3_Under_DUcell3_37 : 48|16@1+ (1,0) [0|65535] "mV"  PC

BO_ 2416701030 S2P_Lmt3__38: 8 SBMU
 SG_ S2P_Lmt3_Over_Ucell3_38 : 0|16@1+ (1,0) [0|65535] "mV"  PC
 SG_ S2P_Lmt3_Over_DUcell3_38 : 16|16@1+ (1,0) [0|65535] "mV"  PC
 SG_ S2P_Lmt3_Under_Ucell3_38 : 32|16@1+ (1,0) [0|65535] "mV"  PC
 SG_ S2P_Lmt3_Under_DUcell3_38 : 48|16@1+ (1,0) [0|65535] "mV"  PC

BO_ 2416701031 S2P_Lmt3__39: 8 SBMU
 SG_ S2P_Lmt3_Over_Ucell3_39 : 0|16@1+ (1,0) [0|65535] "mV"  PC
 SG_ S2P_Lmt3_Over_DUcell3_39 : 16|16@1+ (1,0) [0|65535] "mV"  PC
 SG_ S2P_Lmt3_Under_Ucell3_39 : 32|16@1+ (1,0) [0|65535] "mV"  PC
 SG_ S2P_Lmt3_Under_DUcell3_39 : 48|16@1+ (1,0) [0|65535] "mV"  PC

BO_ 2416701032 S2P_Lmt3__40: 8 SBMU
 SG_ S2P_Lmt3_Over_Ucell3_40 : 0|16@1+ (1,0) [0|65535] "mV"  PC
 SG_ S2P_Lmt3_Over_DUcell3_40 : 16|16@1+ (1,0) [0|65535] "mV"  PC
 SG_ S2P_Lmt3_Under_Ucell3_40 : 32|16@1+ (1,0) [0|65535] "mV"  PC
 SG_ S2P_Lmt3_Under_DUcell3_40 : 48|16@1+ (1,0) [0|65535] "mV"  PC

BO_ 2416701033 S2P_Lmt3__41: 8 SBMU
 SG_ S2P_Lmt3_Over_Ucell3_41 : 0|16@1+ (1,0) [0|65535] "mV"  PC
 SG_ S2P_Lmt3_Over_DUcell3_41 : 16|16@1+ (1,0) [0|65535] "mV"  PC
 SG_ S2P_Lmt3_Under_Ucell3_41 : 32|16@1+ (1,0) [0|65535] "mV"  PC
 SG_ S2P_Lmt3_Under_DUcell3_41 : 48|16@1+ (1,0) [0|65535] "mV"  PC

BO_ 2416701034 S2P_Lmt3__42: 8 SBMU
 SG_ S2P_Lmt3_Over_Ucell3_42 : 0|16@1+ (1,0) [0|65535] "mV"  PC
 SG_ S2P_Lmt3_Over_DUcell3_42 : 16|16@1+ (1,0) [0|65535] "mV"  PC
 SG_ S2P_Lmt3_Under_Ucell3_42 : 32|16@1+ (1,0) [0|65535] "mV"  PC
 SG_ S2P_Lmt3_Under_DUcell3_42 : 48|16@1+ (1,0) [0|65535] "mV"  PC

BO_ 2416701035 S2P_Lmt3__43: 8 SBMU
 SG_ S2P_Lmt3_Over_Ucell3_43 : 0|16@1+ (1,0) [0|65535] "mV"  PC
 SG_ S2P_Lmt3_Over_DUcell3_43 : 16|16@1+ (1,0) [0|65535] "mV"  PC
 SG_ S2P_Lmt3_Under_Ucell3_43 : 32|16@1+ (1,0) [0|65535] "mV"  PC
 SG_ S2P_Lmt3_Under_DUcell3_43 : 48|16@1+ (1,0) [0|65535] "mV"  PC

BO_ 2416701036 S2P_Lmt3__44: 8 SBMU
 SG_ S2P_Lmt3_Over_Ucell3_44 : 0|16@1+ (1,0) [0|65535] "mV"  PC
 SG_ S2P_Lmt3_Over_DUcell3_44 : 16|16@1+ (1,0) [0|65535] "mV"  PC
 SG_ S2P_Lmt3_Under_Ucell3_44 : 32|16@1+ (1,0) [0|65535] "mV"  PC
 SG_ S2P_Lmt3_Under_DUcell3_44 : 48|16@1+ (1,0) [0|65535] "mV"  PC

BO_ 2416701037 S2P_Lmt3__45: 8 SBMU
 SG_ S2P_Lmt3_Over_Ucell3_45 : 0|16@1+ (1,0) [0|65535] "mV"  PC
 SG_ S2P_Lmt3_Over_DUcell3_45 : 16|16@1+ (1,0) [0|65535] "mV"  PC
 SG_ S2P_Lmt3_Under_Ucell3_45 : 32|16@1+ (1,0) [0|65535] "mV"  PC
 SG_ S2P_Lmt3_Under_DUcell3_45 : 48|16@1+ (1,0) [0|65535] "mV"  PC

BO_ 2416701038 S2P_Lmt3__46: 8 SBMU
 SG_ S2P_Lmt3_Over_Ucell3_46 : 0|16@1+ (1,0) [0|65535] "mV"  PC
 SG_ S2P_Lmt3_Over_DUcell3_46 : 16|16@1+ (1,0) [0|65535] "mV"  PC
 SG_ S2P_Lmt3_Under_Ucell3_46 : 32|16@1+ (1,0) [0|65535] "mV"  PC
 SG_ S2P_Lmt3_Under_DUcell3_46 : 48|16@1+ (1,0) [0|65535] "mV"  PC

BO_ 2416701039 S2P_Lmt3__47: 8 SBMU
 SG_ S2P_Lmt3_Over_Ucell3_47 : 0|16@1+ (1,0) [0|65535] "mV"  PC
 SG_ S2P_Lmt3_Over_DUcell3_47 : 16|16@1+ (1,0) [0|65535] "mV"  PC
 SG_ S2P_Lmt3_Under_Ucell3_47 : 32|16@1+ (1,0) [0|65535] "mV"  PC
 SG_ S2P_Lmt3_Under_DUcell3_47 : 48|16@1+ (1,0) [0|65535] "mV"  PC

BO_ 2416701040 S2P_Lmt3__48: 8 SBMU
 SG_ S2P_Lmt3_Over_Ucell3_48 : 0|16@1+ (1,0) [0|65535] "mV"  PC
 SG_ S2P_Lmt3_Over_DUcell3_48 : 16|16@1+ (1,0) [0|65535] "mV"  PC
 SG_ S2P_Lmt3_Under_Ucell3_48 : 32|16@1+ (1,0) [0|65535] "mV"  PC
 SG_ S2P_Lmt3_Under_DUcell3_48 : 48|16@1+ (1,0) [0|65535] "mV"  PC

BO_ 2416701041 S2P_Lmt3__49: 8 SBMU
 SG_ S2P_Lmt3_Over_Ucell3_49 : 0|16@1+ (1,0) [0|65535] "mV"  PC
 SG_ S2P_Lmt3_Over_DUcell3_49 : 16|16@1+ (1,0) [0|65535] "mV"  PC
 SG_ S2P_Lmt3_Under_Ucell3_49 : 32|16@1+ (1,0) [0|65535] "mV"  PC
 SG_ S2P_Lmt3_Under_DUcell3_49 : 48|16@1+ (1,0) [0|65535] "mV"  PC

BO_ 2416701042 S2P_Lmt3__50: 8 SBMU
 SG_ S2P_Lmt3_Over_Ucell3_50 : 0|16@1+ (1,0) [0|65535] "mV"  PC
 SG_ S2P_Lmt3_Over_DUcell3_50 : 16|16@1+ (1,0) [0|65535] "mV"  PC
 SG_ S2P_Lmt3_Under_Ucell3_50 : 32|16@1+ (1,0) [0|65535] "mV"  PC
 SG_ S2P_Lmt3_Under_DUcell3_50 : 48|16@1+ (1,0) [0|65535] "mV"  PC

BO_ 2416701043 S2P_Lmt3__51: 8 SBMU
 SG_ S2P_Lmt3_Over_Ucell3_51 : 0|16@1+ (1,0) [0|65535] "mV"  PC
 SG_ S2P_Lmt3_Over_DUcell3_51 : 16|16@1+ (1,0) [0|65535] "mV"  PC
 SG_ S2P_Lmt3_Under_Ucell3_51 : 32|16@1+ (1,0) [0|65535] "mV"  PC
 SG_ S2P_Lmt3_Under_DUcell3_51 : 48|16@1+ (1,0) [0|65535] "mV"  PC

BO_ 2416701044 S2P_Lmt3__52: 8 SBMU
 SG_ S2P_Lmt3_Over_Ucell3_52 : 0|16@1+ (1,0) [0|65535] "mV"  PC
 SG_ S2P_Lmt3_Over_DUcell3_52 : 16|16@1+ (1,0) [0|65535] "mV"  PC
 SG_ S2P_Lmt3_Under_Ucell3_52 : 32|16@1+ (1,0) [0|65535] "mV"  PC
 SG_ S2P_Lmt3_Under_DUcell3_52 : 48|16@1+ (1,0) [0|65535] "mV"  PC

BO_ 2416701045 S2P_Lmt3__53: 8 SBMU
 SG_ S2P_Lmt3_Over_Ucell3_53 : 0|16@1+ (1,0) [0|65535] "mV"  PC
 SG_ S2P_Lmt3_Over_DUcell3_53 : 16|16@1+ (1,0) [0|65535] "mV"  PC
 SG_ S2P_Lmt3_Under_Ucell3_53 : 32|16@1+ (1,0) [0|65535] "mV"  PC
 SG_ S2P_Lmt3_Under_DUcell3_53 : 48|16@1+ (1,0) [0|65535] "mV"  PC

BO_ 2416701046 S2P_Lmt3__54: 8 SBMU
 SG_ S2P_Lmt3_Over_Ucell3_54 : 0|16@1+ (1,0) [0|65535] "mV"  PC
 SG_ S2P_Lmt3_Over_DUcell3_54 : 16|16@1+ (1,0) [0|65535] "mV"  PC
 SG_ S2P_Lmt3_Under_Ucell3_54 : 32|16@1+ (1,0) [0|65535] "mV"  PC
 SG_ S2P_Lmt3_Under_DUcell3_54 : 48|16@1+ (1,0) [0|65535] "mV"  PC

BO_ 2416701047 S2P_Lmt3__55: 8 SBMU
 SG_ S2P_Lmt3_Over_Ucell3_55 : 0|16@1+ (1,0) [0|65535] "mV"  PC
 SG_ S2P_Lmt3_Over_DUcell3_55 : 16|16@1+ (1,0) [0|65535] "mV"  PC
 SG_ S2P_Lmt3_Under_Ucell3_55 : 32|16@1+ (1,0) [0|65535] "mV"  PC
 SG_ S2P_Lmt3_Under_DUcell3_55 : 48|16@1+ (1,0) [0|65535] "mV"  PC

BO_ 2416701048 S2P_Lmt3__56: 8 SBMU
 SG_ S2P_Lmt3_Over_Ucell3_56 : 0|16@1+ (1,0) [0|65535] "mV"  PC
 SG_ S2P_Lmt3_Over_DUcell3_56 : 16|16@1+ (1,0) [0|65535] "mV"  PC
 SG_ S2P_Lmt3_Under_Ucell3_56 : 32|16@1+ (1,0) [0|65535] "mV"  PC
 SG_ S2P_Lmt3_Under_DUcell3_56 : 48|16@1+ (1,0) [0|65535] "mV"  PC

BO_ 2416701049 S2P_Lmt3__57: 8 SBMU
 SG_ S2P_Lmt3_Over_Ucell3_57 : 0|16@1+ (1,0) [0|65535] "mV"  PC
 SG_ S2P_Lmt3_Over_DUcell3_57 : 16|16@1+ (1,0) [0|65535] "mV"  PC
 SG_ S2P_Lmt3_Under_Ucell3_57 : 32|16@1+ (1,0) [0|65535] "mV"  PC
 SG_ S2P_Lmt3_Under_DUcell3_57 : 48|16@1+ (1,0) [0|65535] "mV"  PC

BO_ 2416701050 S2P_Lmt3__58: 8 SBMU
 SG_ S2P_Lmt3_Over_Ucell3_58 : 0|16@1+ (1,0) [0|65535] "mV"  PC
 SG_ S2P_Lmt3_Over_DUcell3_58 : 16|16@1+ (1,0) [0|65535] "mV"  PC
 SG_ S2P_Lmt3_Under_Ucell3_58 : 32|16@1+ (1,0) [0|65535] "mV"  PC
 SG_ S2P_Lmt3_Under_DUcell3_58 : 48|16@1+ (1,0) [0|65535] "mV"  PC

BO_ 2416701051 S2P_Lmt3__59: 8 SBMU
 SG_ S2P_Lmt3_Over_Ucell3_59 : 0|16@1+ (1,0) [0|65535] "mV"  PC
 SG_ S2P_Lmt3_Over_DUcell3_59 : 16|16@1+ (1,0) [0|65535] "mV"  PC
 SG_ S2P_Lmt3_Under_Ucell3_59 : 32|16@1+ (1,0) [0|65535] "mV"  PC
 SG_ S2P_Lmt3_Under_DUcell3_59 : 48|16@1+ (1,0) [0|65535] "mV"  PC

BO_ 2416701052 S2P_Lmt3__60: 8 SBMU
 SG_ S2P_Lmt3_Over_Ucell3_60 : 0|16@1+ (1,0) [0|65535] "mV"  PC
 SG_ S2P_Lmt3_Over_DUcell3_60 : 16|16@1+ (1,0) [0|65535] "mV"  PC
 SG_ S2P_Lmt3_Under_Ucell3_60 : 32|16@1+ (1,0) [0|65535] "mV"  PC
 SG_ S2P_Lmt3_Under_DUcell3_60 : 48|16@1+ (1,0) [0|65535] "mV"  PC

BO_ 2416701053 S2P_Lmt3__61: 8 SBMU
 SG_ S2P_Lmt3_Over_Ucell3_61 : 0|16@1+ (1,0) [0|65535] "mV"  PC
 SG_ S2P_Lmt3_Over_DUcell3_61 : 16|16@1+ (1,0) [0|65535] "mV"  PC
 SG_ S2P_Lmt3_Under_Ucell3_61 : 32|16@1+ (1,0) [0|65535] "mV"  PC
 SG_ S2P_Lmt3_Under_DUcell3_61 : 48|16@1+ (1,0) [0|65535] "mV"  PC

BO_ 2416701054 S2P_Lmt3__62: 8 SBMU
 SG_ S2P_Lmt3_Over_Ucell3_62 : 0|16@1+ (1,0) [0|65535] "mV"  PC
 SG_ S2P_Lmt3_Over_DUcell3_62 : 16|16@1+ (1,0) [0|65535] "mV"  PC
 SG_ S2P_Lmt3_Under_Ucell3_62 : 32|16@1+ (1,0) [0|65535] "mV"  PC
 SG_ S2P_Lmt3_Under_DUcell3_62 : 48|16@1+ (1,0) [0|65535] "mV"  PC

BO_ 2416701055 S2P_Lmt3__63: 8 SBMU
 SG_ S2P_Lmt3_Over_Ucell3_63 : 0|16@1+ (1,0) [0|65535] "mV"  PC
 SG_ S2P_Lmt3_Over_DUcell3_63 : 16|16@1+ (1,0) [0|65535] "mV"  PC
 SG_ S2P_Lmt3_Under_Ucell3_63 : 32|16@1+ (1,0) [0|65535] "mV"  PC
 SG_ S2P_Lmt3_Under_DUcell3_63 : 48|16@1+ (1,0) [0|65535] "mV"  PC

BO_ 2416766529 S2P_Lmt4__01: 8 SBMU
 SG_ S2P_Lmt4_Over_DeltUcell1_01 : 0|16@1+ (1,0) [0|65535] "mV"  PC
 SG_ S2P_Lmt4_Over_DeltUcell2_01 : 16|16@1+ (1,0) [0|65535] "mV"  PC
 SG_ S2P_Lmt4_Over_DeltUcell3_01 : 32|16@1+ (1,0) [0|65535] "mV"  PC
 SG_ S2P_Lmt4_Over_DDeltUcell_01 : 48|16@1+ (1,0) [0|65535] "mV"  PC

BO_ 2416766530 S2P_Lmt4__02: 8 SBMU
 SG_ S2P_Lmt4_Over_DeltUcell1_02 : 0|16@1+ (1,0) [0|65535] "mV"  PC
 SG_ S2P_Lmt4_Over_DeltUcell2_02 : 16|16@1+ (1,0) [0|65535] "mV"  PC
 SG_ S2P_Lmt4_Over_DeltUcell3_02 : 32|16@1+ (1,0) [0|65535] "mV"  PC
 SG_ S2P_Lmt4_Over_DDeltUcell_02 : 48|16@1+ (1,0) [0|65535] "mV"  PC

BO_ 2416766531 S2P_Lmt4__03: 8 SBMU
 SG_ S2P_Lmt4_Over_DeltUcell1_03 : 0|16@1+ (1,0) [0|65535] "mV"  PC
 SG_ S2P_Lmt4_Over_DeltUcell2_03 : 16|16@1+ (1,0) [0|65535] "mV"  PC
 SG_ S2P_Lmt4_Over_DeltUcell3_03 : 32|16@1+ (1,0) [0|65535] "mV"  PC
 SG_ S2P_Lmt4_Over_DDeltUcell_03 : 48|16@1+ (1,0) [0|65535] "mV"  PC

BO_ 2416766532 S2P_Lmt4__04: 8 SBMU
 SG_ S2P_Lmt4_Over_DeltUcell1_04 : 0|16@1+ (1,0) [0|65535] "mV"  PC
 SG_ S2P_Lmt4_Over_DeltUcell2_04 : 16|16@1+ (1,0) [0|65535] "mV"  PC
 SG_ S2P_Lmt4_Over_DeltUcell3_04 : 32|16@1+ (1,0) [0|65535] "mV"  PC
 SG_ S2P_Lmt4_Over_DDeltUcell_04 : 48|16@1+ (1,0) [0|65535] "mV"  PC

BO_ 2416766533 S2P_Lmt4__05: 8 SBMU
 SG_ S2P_Lmt4_Over_DeltUcell1_05 : 0|16@1+ (1,0) [0|65535] "mV"  PC
 SG_ S2P_Lmt4_Over_DeltUcell2_05 : 16|16@1+ (1,0) [0|65535] "mV"  PC
 SG_ S2P_Lmt4_Over_DeltUcell3_05 : 32|16@1+ (1,0) [0|65535] "mV"  PC
 SG_ S2P_Lmt4_Over_DDeltUcell_05 : 48|16@1+ (1,0) [0|65535] "mV"  PC

BO_ 2416766534 S2P_Lmt4__06: 8 SBMU
 SG_ S2P_Lmt4_Over_DeltUcell1_06 : 0|16@1+ (1,0) [0|65535] "mV"  PC
 SG_ S2P_Lmt4_Over_DeltUcell2_06 : 16|16@1+ (1,0) [0|65535] "mV"  PC
 SG_ S2P_Lmt4_Over_DeltUcell3_06 : 32|16@1+ (1,0) [0|65535] "mV"  PC
 SG_ S2P_Lmt4_Over_DDeltUcell_06 : 48|16@1+ (1,0) [0|65535] "mV"  PC

BO_ 2416766535 S2P_Lmt4__07: 8 SBMU
 SG_ S2P_Lmt4_Over_DeltUcell1_07 : 0|16@1+ (1,0) [0|65535] "mV"  PC
 SG_ S2P_Lmt4_Over_DeltUcell2_07 : 16|16@1+ (1,0) [0|65535] "mV"  PC
 SG_ S2P_Lmt4_Over_DeltUcell3_07 : 32|16@1+ (1,0) [0|65535] "mV"  PC
 SG_ S2P_Lmt4_Over_DDeltUcell_07 : 48|16@1+ (1,0) [0|65535] "mV"  PC

BO_ 2416766536 S2P_Lmt4__08: 8 SBMU
 SG_ S2P_Lmt4_Over_DeltUcell1_08 : 0|16@1+ (1,0) [0|65535] "mV"  PC
 SG_ S2P_Lmt4_Over_DeltUcell2_08 : 16|16@1+ (1,0) [0|65535] "mV"  PC
 SG_ S2P_Lmt4_Over_DeltUcell3_08 : 32|16@1+ (1,0) [0|65535] "mV"  PC
 SG_ S2P_Lmt4_Over_DDeltUcell_08 : 48|16@1+ (1,0) [0|65535] "mV"  PC

BO_ 2416766537 S2P_Lmt4__09: 8 SBMU
 SG_ S2P_Lmt4_Over_DeltUcell1_09 : 0|16@1+ (1,0) [0|65535] "mV"  PC
 SG_ S2P_Lmt4_Over_DeltUcell2_09 : 16|16@1+ (1,0) [0|65535] "mV"  PC
 SG_ S2P_Lmt4_Over_DeltUcell3_09 : 32|16@1+ (1,0) [0|65535] "mV"  PC
 SG_ S2P_Lmt4_Over_DDeltUcell_09 : 48|16@1+ (1,0) [0|65535] "mV"  PC

BO_ 2416766538 S2P_Lmt4__10: 8 SBMU
 SG_ S2P_Lmt4_Over_DeltUcell1_10 : 0|16@1+ (1,0) [0|65535] "mV"  PC
 SG_ S2P_Lmt4_Over_DeltUcell2_10 : 16|16@1+ (1,0) [0|65535] "mV"  PC
 SG_ S2P_Lmt4_Over_DeltUcell3_10 : 32|16@1+ (1,0) [0|65535] "mV"  PC
 SG_ S2P_Lmt4_Over_DDeltUcell_10 : 48|16@1+ (1,0) [0|65535] "mV"  PC

BO_ 2416766539 S2P_Lmt4__11: 8 SBMU
 SG_ S2P_Lmt4_Over_DeltUcell1_11 : 0|16@1+ (1,0) [0|65535] "mV"  PC
 SG_ S2P_Lmt4_Over_DeltUcell2_11 : 16|16@1+ (1,0) [0|65535] "mV"  PC
 SG_ S2P_Lmt4_Over_DeltUcell3_11 : 32|16@1+ (1,0) [0|65535] "mV"  PC
 SG_ S2P_Lmt4_Over_DDeltUcell_11 : 48|16@1+ (1,0) [0|65535] "mV"  PC

BO_ 2416766540 S2P_Lmt4__12: 8 SBMU
 SG_ S2P_Lmt4_Over_DeltUcell1_12 : 0|16@1+ (1,0) [0|65535] "mV"  PC
 SG_ S2P_Lmt4_Over_DeltUcell2_12 : 16|16@1+ (1,0) [0|65535] "mV"  PC
 SG_ S2P_Lmt4_Over_DeltUcell3_12 : 32|16@1+ (1,0) [0|65535] "mV"  PC
 SG_ S2P_Lmt4_Over_DDeltUcell_12 : 48|16@1+ (1,0) [0|65535] "mV"  PC

BO_ 2416766541 S2P_Lmt4__13: 8 SBMU
 SG_ S2P_Lmt4_Over_DeltUcell1_13 : 0|16@1+ (1,0) [0|65535] "mV"  PC
 SG_ S2P_Lmt4_Over_DeltUcell2_13 : 16|16@1+ (1,0) [0|65535] "mV"  PC
 SG_ S2P_Lmt4_Over_DeltUcell3_13 : 32|16@1+ (1,0) [0|65535] "mV"  PC
 SG_ S2P_Lmt4_Over_DDeltUcell_13 : 48|16@1+ (1,0) [0|65535] "mV"  PC

BO_ 2416766542 S2P_Lmt4__14: 8 SBMU
 SG_ S2P_Lmt4_Over_DeltUcell1_14 : 0|16@1+ (1,0) [0|65535] "mV"  PC
 SG_ S2P_Lmt4_Over_DeltUcell2_14 : 16|16@1+ (1,0) [0|65535] "mV"  PC
 SG_ S2P_Lmt4_Over_DeltUcell3_14 : 32|16@1+ (1,0) [0|65535] "mV"  PC
 SG_ S2P_Lmt4_Over_DDeltUcell_14 : 48|16@1+ (1,0) [0|65535] "mV"  PC

BO_ 2416766543 S2P_Lmt4__15: 8 SBMU
 SG_ S2P_Lmt4_Over_DeltUcell1_15 : 0|16@1+ (1,0) [0|65535] "mV"  PC
 SG_ S2P_Lmt4_Over_DeltUcell2_15 : 16|16@1+ (1,0) [0|65535] "mV"  PC
 SG_ S2P_Lmt4_Over_DeltUcell3_15 : 32|16@1+ (1,0) [0|65535] "mV"  PC
 SG_ S2P_Lmt4_Over_DDeltUcell_15 : 48|16@1+ (1,0) [0|65535] "mV"  PC

BO_ 2416766544 S2P_Lmt4__16: 8 SBMU
 SG_ S2P_Lmt4_Over_DeltUcell1_16 : 0|16@1+ (1,0) [0|65535] "mV"  PC
 SG_ S2P_Lmt4_Over_DeltUcell2_16 : 16|16@1+ (1,0) [0|65535] "mV"  PC
 SG_ S2P_Lmt4_Over_DeltUcell3_16 : 32|16@1+ (1,0) [0|65535] "mV"  PC
 SG_ S2P_Lmt4_Over_DDeltUcell_16 : 48|16@1+ (1,0) [0|65535] "mV"  PC

BO_ 2416766545 S2P_Lmt4__17: 8 SBMU
 SG_ S2P_Lmt4_Over_DeltUcell1_17 : 0|16@1+ (1,0) [0|65535] "mV"  PC
 SG_ S2P_Lmt4_Over_DeltUcell2_17 : 16|16@1+ (1,0) [0|65535] "mV"  PC
 SG_ S2P_Lmt4_Over_DeltUcell3_17 : 32|16@1+ (1,0) [0|65535] "mV"  PC
 SG_ S2P_Lmt4_Over_DDeltUcell_17 : 48|16@1+ (1,0) [0|65535] "mV"  PC

BO_ 2416766546 S2P_Lmt4__18: 8 SBMU
 SG_ S2P_Lmt4_Over_DeltUcell1_18 : 0|16@1+ (1,0) [0|65535] "mV"  PC
 SG_ S2P_Lmt4_Over_DeltUcell2_18 : 16|16@1+ (1,0) [0|65535] "mV"  PC
 SG_ S2P_Lmt4_Over_DeltUcell3_18 : 32|16@1+ (1,0) [0|65535] "mV"  PC
 SG_ S2P_Lmt4_Over_DDeltUcell_18 : 48|16@1+ (1,0) [0|65535] "mV"  PC

BO_ 2416766547 S2P_Lmt4__19: 8 SBMU
 SG_ S2P_Lmt4_Over_DeltUcell1_19 : 0|16@1+ (1,0) [0|65535] "mV"  PC
 SG_ S2P_Lmt4_Over_DeltUcell2_19 : 16|16@1+ (1,0) [0|65535] "mV"  PC
 SG_ S2P_Lmt4_Over_DeltUcell3_19 : 32|16@1+ (1,0) [0|65535] "mV"  PC
 SG_ S2P_Lmt4_Over_DDeltUcell_19 : 48|16@1+ (1,0) [0|65535] "mV"  PC

BO_ 2416766548 S2P_Lmt4__20: 8 SBMU
 SG_ S2P_Lmt4_Over_DeltUcell1_20 : 0|16@1+ (1,0) [0|65535] "mV"  PC
 SG_ S2P_Lmt4_Over_DeltUcell2_20 : 16|16@1+ (1,0) [0|65535] "mV"  PC
 SG_ S2P_Lmt4_Over_DeltUcell3_20 : 32|16@1+ (1,0) [0|65535] "mV"  PC
 SG_ S2P_Lmt4_Over_DDeltUcell_20 : 48|16@1+ (1,0) [0|65535] "mV"  PC

BO_ 2416766549 S2P_Lmt4__21: 8 SBMU
 SG_ S2P_Lmt4_Over_DeltUcell1_21 : 0|16@1+ (1,0) [0|65535] "mV"  PC
 SG_ S2P_Lmt4_Over_DeltUcell2_21 : 16|16@1+ (1,0) [0|65535] "mV"  PC
 SG_ S2P_Lmt4_Over_DeltUcell3_21 : 32|16@1+ (1,0) [0|65535] "mV"  PC
 SG_ S2P_Lmt4_Over_DDeltUcell_21 : 48|16@1+ (1,0) [0|65535] "mV"  PC

BO_ 2416766550 S2P_Lmt4__22: 8 SBMU
 SG_ S2P_Lmt4_Over_DeltUcell1_22 : 0|16@1+ (1,0) [0|65535] "mV"  PC
 SG_ S2P_Lmt4_Over_DeltUcell2_22 : 16|16@1+ (1,0) [0|65535] "mV"  PC
 SG_ S2P_Lmt4_Over_DeltUcell3_22 : 32|16@1+ (1,0) [0|65535] "mV"  PC
 SG_ S2P_Lmt4_Over_DDeltUcell_22 : 48|16@1+ (1,0) [0|65535] "mV"  PC

BO_ 2416766551 S2P_Lmt4__23: 8 SBMU
 SG_ S2P_Lmt4_Over_DeltUcell1_23 : 0|16@1+ (1,0) [0|65535] "mV"  PC
 SG_ S2P_Lmt4_Over_DeltUcell2_23 : 16|16@1+ (1,0) [0|65535] "mV"  PC
 SG_ S2P_Lmt4_Over_DeltUcell3_23 : 32|16@1+ (1,0) [0|65535] "mV"  PC
 SG_ S2P_Lmt4_Over_DDeltUcell_23 : 48|16@1+ (1,0) [0|65535] "mV"  PC

BO_ 2416766552 S2P_Lmt4__24: 8 SBMU
 SG_ S2P_Lmt4_Over_DeltUcell1_24 : 0|16@1+ (1,0) [0|65535] "mV"  PC
 SG_ S2P_Lmt4_Over_DeltUcell2_24 : 16|16@1+ (1,0) [0|65535] "mV"  PC
 SG_ S2P_Lmt4_Over_DeltUcell3_24 : 32|16@1+ (1,0) [0|65535] "mV"  PC
 SG_ S2P_Lmt4_Over_DDeltUcell_24 : 48|16@1+ (1,0) [0|65535] "mV"  PC

BO_ 2416766553 S2P_Lmt4__25: 8 SBMU
 SG_ S2P_Lmt4_Over_DeltUcell1_25 : 0|16@1+ (1,0) [0|65535] "mV"  PC
 SG_ S2P_Lmt4_Over_DeltUcell2_25 : 16|16@1+ (1,0) [0|65535] "mV"  PC
 SG_ S2P_Lmt4_Over_DeltUcell3_25 : 32|16@1+ (1,0) [0|65535] "mV"  PC
 SG_ S2P_Lmt4_Over_DDeltUcell_25 : 48|16@1+ (1,0) [0|65535] "mV"  PC

BO_ 2416766554 S2P_Lmt4__26: 8 SBMU
 SG_ S2P_Lmt4_Over_DeltUcell1_26 : 0|16@1+ (1,0) [0|65535] "mV"  PC
 SG_ S2P_Lmt4_Over_DeltUcell2_26 : 16|16@1+ (1,0) [0|65535] "mV"  PC
 SG_ S2P_Lmt4_Over_DeltUcell3_26 : 32|16@1+ (1,0) [0|65535] "mV"  PC
 SG_ S2P_Lmt4_Over_DDeltUcell_26 : 48|16@1+ (1,0) [0|65535] "mV"  PC

BO_ 2416766555 S2P_Lmt4__27: 8 SBMU
 SG_ S2P_Lmt4_Over_DeltUcell1_27 : 0|16@1+ (1,0) [0|65535] "mV"  PC
 SG_ S2P_Lmt4_Over_DeltUcell2_27 : 16|16@1+ (1,0) [0|65535] "mV"  PC
 SG_ S2P_Lmt4_Over_DeltUcell3_27 : 32|16@1+ (1,0) [0|65535] "mV"  PC
 SG_ S2P_Lmt4_Over_DDeltUcell_27 : 48|16@1+ (1,0) [0|65535] "mV"  PC

BO_ 2416766556 S2P_Lmt4__28: 8 SBMU
 SG_ S2P_Lmt4_Over_DeltUcell1_28 : 0|16@1+ (1,0) [0|65535] "mV"  PC
 SG_ S2P_Lmt4_Over_DeltUcell2_28 : 16|16@1+ (1,0) [0|65535] "mV"  PC
 SG_ S2P_Lmt4_Over_DeltUcell3_28 : 32|16@1+ (1,0) [0|65535] "mV"  PC
 SG_ S2P_Lmt4_Over_DDeltUcell_28 : 48|16@1+ (1,0) [0|65535] "mV"  PC

BO_ 2416766557 S2P_Lmt4__29: 8 SBMU
 SG_ S2P_Lmt4_Over_DeltUcell1_29 : 0|16@1+ (1,0) [0|65535] "mV"  PC
 SG_ S2P_Lmt4_Over_DeltUcell2_29 : 16|16@1+ (1,0) [0|65535] "mV"  PC
 SG_ S2P_Lmt4_Over_DeltUcell3_29 : 32|16@1+ (1,0) [0|65535] "mV"  PC
 SG_ S2P_Lmt4_Over_DDeltUcell_29 : 48|16@1+ (1,0) [0|65535] "mV"  PC

BO_ 2416766558 S2P_Lmt4__30: 8 SBMU
 SG_ S2P_Lmt4_Over_DeltUcell1_30 : 0|16@1+ (1,0) [0|65535] "mV"  PC
 SG_ S2P_Lmt4_Over_DeltUcell2_30 : 16|16@1+ (1,0) [0|65535] "mV"  PC
 SG_ S2P_Lmt4_Over_DeltUcell3_30 : 32|16@1+ (1,0) [0|65535] "mV"  PC
 SG_ S2P_Lmt4_Over_DDeltUcell_30 : 48|16@1+ (1,0) [0|65535] "mV"  PC

BO_ 2416766559 S2P_Lmt4__31: 8 SBMU
 SG_ S2P_Lmt4_Over_DeltUcell1_31 : 0|16@1+ (1,0) [0|65535] "mV"  PC
 SG_ S2P_Lmt4_Over_DeltUcell2_31 : 16|16@1+ (1,0) [0|65535] "mV"  PC
 SG_ S2P_Lmt4_Over_DeltUcell3_31 : 32|16@1+ (1,0) [0|65535] "mV"  PC
 SG_ S2P_Lmt4_Over_DDeltUcell_31 : 48|16@1+ (1,0) [0|65535] "mV"  PC

BO_ 2416766560 S2P_Lmt4__32: 8 SBMU
 SG_ S2P_Lmt4_Over_DeltUcell1_32 : 0|16@1+ (1,0) [0|65535] "mV"  PC
 SG_ S2P_Lmt4_Over_DeltUcell2_32 : 16|16@1+ (1,0) [0|65535] "mV"  PC
 SG_ S2P_Lmt4_Over_DeltUcell3_32 : 32|16@1+ (1,0) [0|65535] "mV"  PC
 SG_ S2P_Lmt4_Over_DDeltUcell_32 : 48|16@1+ (1,0) [0|65535] "mV"  PC

BO_ 2416766561 S2P_Lmt4__33: 8 SBMU
 SG_ S2P_Lmt4_Over_DeltUcell1_33 : 0|16@1+ (1,0) [0|65535] "mV"  PC
 SG_ S2P_Lmt4_Over_DeltUcell2_33 : 16|16@1+ (1,0) [0|65535] "mV"  PC
 SG_ S2P_Lmt4_Over_DeltUcell3_33 : 32|16@1+ (1,0) [0|65535] "mV"  PC
 SG_ S2P_Lmt4_Over_DDeltUcell_33 : 48|16@1+ (1,0) [0|65535] "mV"  PC

BO_ 2416766562 S2P_Lmt4__34: 8 SBMU
 SG_ S2P_Lmt4_Over_DeltUcell1_34 : 0|16@1+ (1,0) [0|65535] "mV"  PC
 SG_ S2P_Lmt4_Over_DeltUcell2_34 : 16|16@1+ (1,0) [0|65535] "mV"  PC
 SG_ S2P_Lmt4_Over_DeltUcell3_34 : 32|16@1+ (1,0) [0|65535] "mV"  PC
 SG_ S2P_Lmt4_Over_DDeltUcell_34 : 48|16@1+ (1,0) [0|65535] "mV"  PC

BO_ 2416766563 S2P_Lmt4__35: 8 SBMU
 SG_ S2P_Lmt4_Over_DeltUcell1_35 : 0|16@1+ (1,0) [0|65535] "mV"  PC
 SG_ S2P_Lmt4_Over_DeltUcell2_35 : 16|16@1+ (1,0) [0|65535] "mV"  PC
 SG_ S2P_Lmt4_Over_DeltUcell3_35 : 32|16@1+ (1,0) [0|65535] "mV"  PC
 SG_ S2P_Lmt4_Over_DDeltUcell_35 : 48|16@1+ (1,0) [0|65535] "mV"  PC

BO_ 2416766564 S2P_Lmt4__36: 8 SBMU
 SG_ S2P_Lmt4_Over_DeltUcell1_36 : 0|16@1+ (1,0) [0|65535] "mV"  PC
 SG_ S2P_Lmt4_Over_DeltUcell2_36 : 16|16@1+ (1,0) [0|65535] "mV"  PC
 SG_ S2P_Lmt4_Over_DeltUcell3_36 : 32|16@1+ (1,0) [0|65535] "mV"  PC
 SG_ S2P_Lmt4_Over_DDeltUcell_36 : 48|16@1+ (1,0) [0|65535] "mV"  PC

BO_ 2416766565 S2P_Lmt4__37: 8 SBMU
 SG_ S2P_Lmt4_Over_DeltUcell1_37 : 0|16@1+ (1,0) [0|65535] "mV"  PC
 SG_ S2P_Lmt4_Over_DeltUcell2_37 : 16|16@1+ (1,0) [0|65535] "mV"  PC
 SG_ S2P_Lmt4_Over_DeltUcell3_37 : 32|16@1+ (1,0) [0|65535] "mV"  PC
 SG_ S2P_Lmt4_Over_DDeltUcell_37 : 48|16@1+ (1,0) [0|65535] "mV"  PC

BO_ 2416766566 S2P_Lmt4__38: 8 SBMU
 SG_ S2P_Lmt4_Over_DeltUcell1_38 : 0|16@1+ (1,0) [0|65535] "mV"  PC
 SG_ S2P_Lmt4_Over_DeltUcell2_38 : 16|16@1+ (1,0) [0|65535] "mV"  PC
 SG_ S2P_Lmt4_Over_DeltUcell3_38 : 32|16@1+ (1,0) [0|65535] "mV"  PC
 SG_ S2P_Lmt4_Over_DDeltUcell_38 : 48|16@1+ (1,0) [0|65535] "mV"  PC

BO_ 2416766567 S2P_Lmt4__39: 8 SBMU
 SG_ S2P_Lmt4_Over_DeltUcell1_39 : 0|16@1+ (1,0) [0|65535] "mV"  PC
 SG_ S2P_Lmt4_Over_DeltUcell2_39 : 16|16@1+ (1,0) [0|65535] "mV"  PC
 SG_ S2P_Lmt4_Over_DeltUcell3_39 : 32|16@1+ (1,0) [0|65535] "mV"  PC
 SG_ S2P_Lmt4_Over_DDeltUcell_39 : 48|16@1+ (1,0) [0|65535] "mV"  PC

BO_ 2416766568 S2P_Lmt4__40: 8 SBMU
 SG_ S2P_Lmt4_Over_DeltUcell1_40 : 0|16@1+ (1,0) [0|65535] "mV"  PC
 SG_ S2P_Lmt4_Over_DeltUcell2_40 : 16|16@1+ (1,0) [0|65535] "mV"  PC
 SG_ S2P_Lmt4_Over_DeltUcell3_40 : 32|16@1+ (1,0) [0|65535] "mV"  PC
 SG_ S2P_Lmt4_Over_DDeltUcell_40 : 48|16@1+ (1,0) [0|65535] "mV"  PC

BO_ 2416766569 S2P_Lmt4__41: 8 SBMU
 SG_ S2P_Lmt4_Over_DeltUcell1_41 : 0|16@1+ (1,0) [0|65535] "mV"  PC
 SG_ S2P_Lmt4_Over_DeltUcell2_41 : 16|16@1+ (1,0) [0|65535] "mV"  PC
 SG_ S2P_Lmt4_Over_DeltUcell3_41 : 32|16@1+ (1,0) [0|65535] "mV"  PC
 SG_ S2P_Lmt4_Over_DDeltUcell_41 : 48|16@1+ (1,0) [0|65535] "mV"  PC

BO_ 2416766570 S2P_Lmt4__42: 8 SBMU
 SG_ S2P_Lmt4_Over_DeltUcell1_42 : 0|16@1+ (1,0) [0|65535] "mV"  PC
 SG_ S2P_Lmt4_Over_DeltUcell2_42 : 16|16@1+ (1,0) [0|65535] "mV"  PC
 SG_ S2P_Lmt4_Over_DeltUcell3_42 : 32|16@1+ (1,0) [0|65535] "mV"  PC
 SG_ S2P_Lmt4_Over_DDeltUcell_42 : 48|16@1+ (1,0) [0|65535] "mV"  PC

BO_ 2416766571 S2P_Lmt4__43: 8 SBMU
 SG_ S2P_Lmt4_Over_DeltUcell1_43 : 0|16@1+ (1,0) [0|65535] "mV"  PC
 SG_ S2P_Lmt4_Over_DeltUcell2_43 : 16|16@1+ (1,0) [0|65535] "mV"  PC
 SG_ S2P_Lmt4_Over_DeltUcell3_43 : 32|16@1+ (1,0) [0|65535] "mV"  PC
 SG_ S2P_Lmt4_Over_DDeltUcell_43 : 48|16@1+ (1,0) [0|65535] "mV"  PC

BO_ 2416766572 S2P_Lmt4__44: 8 SBMU
 SG_ S2P_Lmt4_Over_DeltUcell1_44 : 0|16@1+ (1,0) [0|65535] "mV"  PC
 SG_ S2P_Lmt4_Over_DeltUcell2_44 : 16|16@1+ (1,0) [0|65535] "mV"  PC
 SG_ S2P_Lmt4_Over_DeltUcell3_44 : 32|16@1+ (1,0) [0|65535] "mV"  PC
 SG_ S2P_Lmt4_Over_DDeltUcell_44 : 48|16@1+ (1,0) [0|65535] "mV"  PC

BO_ 2416766573 S2P_Lmt4__45: 8 SBMU
 SG_ S2P_Lmt4_Over_DeltUcell1_45 : 0|16@1+ (1,0) [0|65535] "mV"  PC
 SG_ S2P_Lmt4_Over_DeltUcell2_45 : 16|16@1+ (1,0) [0|65535] "mV"  PC
 SG_ S2P_Lmt4_Over_DeltUcell3_45 : 32|16@1+ (1,0) [0|65535] "mV"  PC
 SG_ S2P_Lmt4_Over_DDeltUcell_45 : 48|16@1+ (1,0) [0|65535] "mV"  PC

BO_ 2416766574 S2P_Lmt4__46: 8 SBMU
 SG_ S2P_Lmt4_Over_DeltUcell1_46 : 0|16@1+ (1,0) [0|65535] "mV"  PC
 SG_ S2P_Lmt4_Over_DeltUcell2_46 : 16|16@1+ (1,0) [0|65535] "mV"  PC
 SG_ S2P_Lmt4_Over_DeltUcell3_46 : 32|16@1+ (1,0) [0|65535] "mV"  PC
 SG_ S2P_Lmt4_Over_DDeltUcell_46 : 48|16@1+ (1,0) [0|65535] "mV"  PC

BO_ 2416766575 S2P_Lmt4__47: 8 SBMU
 SG_ S2P_Lmt4_Over_DeltUcell1_47 : 0|16@1+ (1,0) [0|65535] "mV"  PC
 SG_ S2P_Lmt4_Over_DeltUcell2_47 : 16|16@1+ (1,0) [0|65535] "mV"  PC
 SG_ S2P_Lmt4_Over_DeltUcell3_47 : 32|16@1+ (1,0) [0|65535] "mV"  PC
 SG_ S2P_Lmt4_Over_DDeltUcell_47 : 48|16@1+ (1,0) [0|65535] "mV"  PC

BO_ 2416766576 S2P_Lmt4__48: 8 SBMU
 SG_ S2P_Lmt4_Over_DeltUcell1_48 : 0|16@1+ (1,0) [0|65535] "mV"  PC
 SG_ S2P_Lmt4_Over_DeltUcell2_48 : 16|16@1+ (1,0) [0|65535] "mV"  PC
 SG_ S2P_Lmt4_Over_DeltUcell3_48 : 32|16@1+ (1,0) [0|65535] "mV"  PC
 SG_ S2P_Lmt4_Over_DDeltUcell_48 : 48|16@1+ (1,0) [0|65535] "mV"  PC

BO_ 2416766577 S2P_Lmt4__49: 8 SBMU
 SG_ S2P_Lmt4_Over_DeltUcell1_49 : 0|16@1+ (1,0) [0|65535] "mV"  PC
 SG_ S2P_Lmt4_Over_DeltUcell2_49 : 16|16@1+ (1,0) [0|65535] "mV"  PC
 SG_ S2P_Lmt4_Over_DeltUcell3_49 : 32|16@1+ (1,0) [0|65535] "mV"  PC
 SG_ S2P_Lmt4_Over_DDeltUcell_49 : 48|16@1+ (1,0) [0|65535] "mV"  PC

BO_ 2416766578 S2P_Lmt4__50: 8 SBMU
 SG_ S2P_Lmt4_Over_DeltUcell1_50 : 0|16@1+ (1,0) [0|65535] "mV"  PC
 SG_ S2P_Lmt4_Over_DeltUcell2_50 : 16|16@1+ (1,0) [0|65535] "mV"  PC
 SG_ S2P_Lmt4_Over_DeltUcell3_50 : 32|16@1+ (1,0) [0|65535] "mV"  PC
 SG_ S2P_Lmt4_Over_DDeltUcell_50 : 48|16@1+ (1,0) [0|65535] "mV"  PC

BO_ 2416766579 S2P_Lmt4__51: 8 SBMU
 SG_ S2P_Lmt4_Over_DeltUcell1_51 : 0|16@1+ (1,0) [0|65535] "mV"  PC
 SG_ S2P_Lmt4_Over_DeltUcell2_51 : 16|16@1+ (1,0) [0|65535] "mV"  PC
 SG_ S2P_Lmt4_Over_DeltUcell3_51 : 32|16@1+ (1,0) [0|65535] "mV"  PC
 SG_ S2P_Lmt4_Over_DDeltUcell_51 : 48|16@1+ (1,0) [0|65535] "mV"  PC

BO_ 2416766580 S2P_Lmt4__52: 8 SBMU
 SG_ S2P_Lmt4_Over_DeltUcell1_52 : 0|16@1+ (1,0) [0|65535] "mV"  PC
 SG_ S2P_Lmt4_Over_DeltUcell2_52 : 16|16@1+ (1,0) [0|65535] "mV"  PC
 SG_ S2P_Lmt4_Over_DeltUcell3_52 : 32|16@1+ (1,0) [0|65535] "mV"  PC
 SG_ S2P_Lmt4_Over_DDeltUcell_52 : 48|16@1+ (1,0) [0|65535] "mV"  PC

BO_ 2416766581 S2P_Lmt4__53: 8 SBMU
 SG_ S2P_Lmt4_Over_DeltUcell1_53 : 0|16@1+ (1,0) [0|65535] "mV"  PC
 SG_ S2P_Lmt4_Over_DeltUcell2_53 : 16|16@1+ (1,0) [0|65535] "mV"  PC
 SG_ S2P_Lmt4_Over_DeltUcell3_53 : 32|16@1+ (1,0) [0|65535] "mV"  PC
 SG_ S2P_Lmt4_Over_DDeltUcell_53 : 48|16@1+ (1,0) [0|65535] "mV"  PC

BO_ 2416766582 S2P_Lmt4__54: 8 SBMU
 SG_ S2P_Lmt4_Over_DeltUcell1_54 : 0|16@1+ (1,0) [0|65535] "mV"  PC
 SG_ S2P_Lmt4_Over_DeltUcell2_54 : 16|16@1+ (1,0) [0|65535] "mV"  PC
 SG_ S2P_Lmt4_Over_DeltUcell3_54 : 32|16@1+ (1,0) [0|65535] "mV"  PC
 SG_ S2P_Lmt4_Over_DDeltUcell_54 : 48|16@1+ (1,0) [0|65535] "mV"  PC

BO_ 2416766583 S2P_Lmt4__55: 8 SBMU
 SG_ S2P_Lmt4_Over_DeltUcell1_55 : 0|16@1+ (1,0) [0|65535] "mV"  PC
 SG_ S2P_Lmt4_Over_DeltUcell2_55 : 16|16@1+ (1,0) [0|65535] "mV"  PC
 SG_ S2P_Lmt4_Over_DeltUcell3_55 : 32|16@1+ (1,0) [0|65535] "mV"  PC
 SG_ S2P_Lmt4_Over_DDeltUcell_55 : 48|16@1+ (1,0) [0|65535] "mV"  PC

BO_ 2416766584 S2P_Lmt4__56: 8 SBMU
 SG_ S2P_Lmt4_Over_DeltUcell1_56 : 0|16@1+ (1,0) [0|65535] "mV"  PC
 SG_ S2P_Lmt4_Over_DeltUcell2_56 : 16|16@1+ (1,0) [0|65535] "mV"  PC
 SG_ S2P_Lmt4_Over_DeltUcell3_56 : 32|16@1+ (1,0) [0|65535] "mV"  PC
 SG_ S2P_Lmt4_Over_DDeltUcell_56 : 48|16@1+ (1,0) [0|65535] "mV"  PC

BO_ 2416766585 S2P_Lmt4__57: 8 SBMU
 SG_ S2P_Lmt4_Over_DeltUcell1_57 : 0|16@1+ (1,0) [0|65535] "mV"  PC
 SG_ S2P_Lmt4_Over_DeltUcell2_57 : 16|16@1+ (1,0) [0|65535] "mV"  PC
 SG_ S2P_Lmt4_Over_DeltUcell3_57 : 32|16@1+ (1,0) [0|65535] "mV"  PC
 SG_ S2P_Lmt4_Over_DDeltUcell_57 : 48|16@1+ (1,0) [0|65535] "mV"  PC

BO_ 2416766586 S2P_Lmt4__58: 8 SBMU
 SG_ S2P_Lmt4_Over_DeltUcell1_58 : 0|16@1+ (1,0) [0|65535] "mV"  PC
 SG_ S2P_Lmt4_Over_DeltUcell2_58 : 16|16@1+ (1,0) [0|65535] "mV"  PC
 SG_ S2P_Lmt4_Over_DeltUcell3_58 : 32|16@1+ (1,0) [0|65535] "mV"  PC
 SG_ S2P_Lmt4_Over_DDeltUcell_58 : 48|16@1+ (1,0) [0|65535] "mV"  PC

BO_ 2416766587 S2P_Lmt4__59: 8 SBMU
 SG_ S2P_Lmt4_Over_DeltUcell1_59 : 0|16@1+ (1,0) [0|65535] "mV"  PC
 SG_ S2P_Lmt4_Over_DeltUcell2_59 : 16|16@1+ (1,0) [0|65535] "mV"  PC
 SG_ S2P_Lmt4_Over_DeltUcell3_59 : 32|16@1+ (1,0) [0|65535] "mV"  PC
 SG_ S2P_Lmt4_Over_DDeltUcell_59 : 48|16@1+ (1,0) [0|65535] "mV"  PC

BO_ 2416766588 S2P_Lmt4__60: 8 SBMU
 SG_ S2P_Lmt4_Over_DeltUcell1_60 : 0|16@1+ (1,0) [0|65535] "mV"  PC
 SG_ S2P_Lmt4_Over_DeltUcell2_60 : 16|16@1+ (1,0) [0|65535] "mV"  PC
 SG_ S2P_Lmt4_Over_DeltUcell3_60 : 32|16@1+ (1,0) [0|65535] "mV"  PC
 SG_ S2P_Lmt4_Over_DDeltUcell_60 : 48|16@1+ (1,0) [0|65535] "mV"  PC

BO_ 2416766589 S2P_Lmt4__61: 8 SBMU
 SG_ S2P_Lmt4_Over_DeltUcell1_61 : 0|16@1+ (1,0) [0|65535] "mV"  PC
 SG_ S2P_Lmt4_Over_DeltUcell2_61 : 16|16@1+ (1,0) [0|65535] "mV"  PC
 SG_ S2P_Lmt4_Over_DeltUcell3_61 : 32|16@1+ (1,0) [0|65535] "mV"  PC
 SG_ S2P_Lmt4_Over_DDeltUcell_61 : 48|16@1+ (1,0) [0|65535] "mV"  PC

BO_ 2416766590 S2P_Lmt4__62: 8 SBMU
 SG_ S2P_Lmt4_Over_DeltUcell1_62 : 0|16@1+ (1,0) [0|65535] "mV"  PC
 SG_ S2P_Lmt4_Over_DeltUcell2_62 : 16|16@1+ (1,0) [0|65535] "mV"  PC
 SG_ S2P_Lmt4_Over_DeltUcell3_62 : 32|16@1+ (1,0) [0|65535] "mV"  PC
 SG_ S2P_Lmt4_Over_DDeltUcell_62 : 48|16@1+ (1,0) [0|65535] "mV"  PC

BO_ 2416766591 S2P_Lmt4__63: 8 SBMU
 SG_ S2P_Lmt4_Over_DeltUcell1_63 : 0|16@1+ (1,0) [0|65535] "mV"  PC
 SG_ S2P_Lmt4_Over_DeltUcell2_63 : 16|16@1+ (1,0) [0|65535] "mV"  PC
 SG_ S2P_Lmt4_Over_DeltUcell3_63 : 32|16@1+ (1,0) [0|65535] "mV"  PC
 SG_ S2P_Lmt4_Over_DDeltUcell_63 : 48|16@1+ (1,0) [0|65535] "mV"  PC

BO_ 2416832065 S2P_Lmt5__01: 8 SBMU
 SG_ S2P_Lmt5_Over_Utank1_01 : 0|16@1+ (0.1,0) [0|6553.5] "V"  PC
 SG_ S2P_Lmt5_Over_Utank2_01 : 16|16@1+ (0.1,0) [0|6553.5] "V"  PC
 SG_ S2P_Lmt5_Over_Utank3_01 : 32|16@1+ (0.1,0) [0|6553.5] "V"  PC
 SG_ S2P_Lmt5_Over_DUtank_01 : 48|16@1+ (0.1,0) [0|6553.5] "V"  PC

BO_ 2416832066 S2P_Lmt5__02: 8 SBMU
 SG_ S2P_Lmt5_Over_Utank1_02 : 0|16@1+ (0.1,0) [0|6553.5] "V"  PC
 SG_ S2P_Lmt5_Over_Utank2_02 : 16|16@1+ (0.1,0) [0|6553.5] "V"  PC
 SG_ S2P_Lmt5_Over_Utank3_02 : 32|16@1+ (0.1,0) [0|6553.5] "V"  PC
 SG_ S2P_Lmt5_Over_DUtank_02 : 48|16@1+ (0.1,0) [0|6553.5] "V"  PC

BO_ 2416832067 S2P_Lmt5__03: 8 SBMU
 SG_ S2P_Lmt5_Over_Utank1_03 : 0|16@1+ (0.1,0) [0|6553.5] "V"  PC
 SG_ S2P_Lmt5_Over_Utank2_03 : 16|16@1+ (0.1,0) [0|6553.5] "V"  PC
 SG_ S2P_Lmt5_Over_Utank3_03 : 32|16@1+ (0.1,0) [0|6553.5] "V"  PC
 SG_ S2P_Lmt5_Over_DUtank_03 : 48|16@1+ (0.1,0) [0|6553.5] "V"  PC

BO_ 2416832068 S2P_Lmt5__04: 8 SBMU
 SG_ S2P_Lmt5_Over_Utank1_04 : 0|16@1+ (0.1,0) [0|6553.5] "V"  PC
 SG_ S2P_Lmt5_Over_Utank2_04 : 16|16@1+ (0.1,0) [0|6553.5] "V"  PC
 SG_ S2P_Lmt5_Over_Utank3_04 : 32|16@1+ (0.1,0) [0|6553.5] "V"  PC
 SG_ S2P_Lmt5_Over_DUtank_04 : 48|16@1+ (0.1,0) [0|6553.5] "V"  PC

BO_ 2416832069 S2P_Lmt5__05: 8 SBMU
 SG_ S2P_Lmt5_Over_Utank1_05 : 0|16@1+ (0.1,0) [0|6553.5] "V"  PC
 SG_ S2P_Lmt5_Over_Utank2_05 : 16|16@1+ (0.1,0) [0|6553.5] "V"  PC
 SG_ S2P_Lmt5_Over_Utank3_05 : 32|16@1+ (0.1,0) [0|6553.5] "V"  PC
 SG_ S2P_Lmt5_Over_DUtank_05 : 48|16@1+ (0.1,0) [0|6553.5] "V"  PC

BO_ 2416832070 S2P_Lmt5__06: 8 SBMU
 SG_ S2P_Lmt5_Over_Utank1_06 : 0|16@1+ (0.1,0) [0|6553.5] "V"  PC
 SG_ S2P_Lmt5_Over_Utank2_06 : 16|16@1+ (0.1,0) [0|6553.5] "V"  PC
 SG_ S2P_Lmt5_Over_Utank3_06 : 32|16@1+ (0.1,0) [0|6553.5] "V"  PC
 SG_ S2P_Lmt5_Over_DUtank_06 : 48|16@1+ (0.1,0) [0|6553.5] "V"  PC

BO_ 2416832071 S2P_Lmt5__07: 8 SBMU
 SG_ S2P_Lmt5_Over_Utank1_07 : 0|16@1+ (0.1,0) [0|6553.5] "V"  PC
 SG_ S2P_Lmt5_Over_Utank2_07 : 16|16@1+ (0.1,0) [0|6553.5] "V"  PC
 SG_ S2P_Lmt5_Over_Utank3_07 : 32|16@1+ (0.1,0) [0|6553.5] "V"  PC
 SG_ S2P_Lmt5_Over_DUtank_07 : 48|16@1+ (0.1,0) [0|6553.5] "V"  PC

BO_ 2416832072 S2P_Lmt5__08: 8 SBMU
 SG_ S2P_Lmt5_Over_Utank1_08 : 0|16@1+ (0.1,0) [0|6553.5] "V"  PC
 SG_ S2P_Lmt5_Over_Utank2_08 : 16|16@1+ (0.1,0) [0|6553.5] "V"  PC
 SG_ S2P_Lmt5_Over_Utank3_08 : 32|16@1+ (0.1,0) [0|6553.5] "V"  PC
 SG_ S2P_Lmt5_Over_DUtank_08 : 48|16@1+ (0.1,0) [0|6553.5] "V"  PC

BO_ 2416832073 S2P_Lmt5__09: 8 SBMU
 SG_ S2P_Lmt5_Over_Utank1_09 : 0|16@1+ (0.1,0) [0|6553.5] "V"  PC
 SG_ S2P_Lmt5_Over_Utank2_09 : 16|16@1+ (0.1,0) [0|6553.5] "V"  PC
 SG_ S2P_Lmt5_Over_Utank3_09 : 32|16@1+ (0.1,0) [0|6553.5] "V"  PC
 SG_ S2P_Lmt5_Over_DUtank_09 : 48|16@1+ (0.1,0) [0|6553.5] "V"  PC

BO_ 2416832074 S2P_Lmt5__10: 8 SBMU
 SG_ S2P_Lmt5_Over_Utank1_10 : 0|16@1+ (0.1,0) [0|6553.5] "V"  PC
 SG_ S2P_Lmt5_Over_Utank2_10 : 16|16@1+ (0.1,0) [0|6553.5] "V"  PC
 SG_ S2P_Lmt5_Over_Utank3_10 : 32|16@1+ (0.1,0) [0|6553.5] "V"  PC
 SG_ S2P_Lmt5_Over_DUtank_10 : 48|16@1+ (0.1,0) [0|6553.5] "V"  PC

BO_ 2416832075 S2P_Lmt5__11: 8 SBMU
 SG_ S2P_Lmt5_Over_Utank1_11 : 0|16@1+ (0.1,0) [0|6553.5] "V"  PC
 SG_ S2P_Lmt5_Over_Utank2_11 : 16|16@1+ (0.1,0) [0|6553.5] "V"  PC
 SG_ S2P_Lmt5_Over_Utank3_11 : 32|16@1+ (0.1,0) [0|6553.5] "V"  PC
 SG_ S2P_Lmt5_Over_DUtank_11 : 48|16@1+ (0.1,0) [0|6553.5] "V"  PC

BO_ 2416832076 S2P_Lmt5__12: 8 SBMU
 SG_ S2P_Lmt5_Over_Utank1_12 : 0|16@1+ (0.1,0) [0|6553.5] "V"  PC
 SG_ S2P_Lmt5_Over_Utank2_12 : 16|16@1+ (0.1,0) [0|6553.5] "V"  PC
 SG_ S2P_Lmt5_Over_Utank3_12 : 32|16@1+ (0.1,0) [0|6553.5] "V"  PC
 SG_ S2P_Lmt5_Over_DUtank_12 : 48|16@1+ (0.1,0) [0|6553.5] "V"  PC

BO_ 2416832077 S2P_Lmt5__13: 8 SBMU
 SG_ S2P_Lmt5_Over_Utank1_13 : 0|16@1+ (0.1,0) [0|6553.5] "V"  PC
 SG_ S2P_Lmt5_Over_Utank2_13 : 16|16@1+ (0.1,0) [0|6553.5] "V"  PC
 SG_ S2P_Lmt5_Over_Utank3_13 : 32|16@1+ (0.1,0) [0|6553.5] "V"  PC
 SG_ S2P_Lmt5_Over_DUtank_13 : 48|16@1+ (0.1,0) [0|6553.5] "V"  PC

BO_ 2416832078 S2P_Lmt5__14: 8 SBMU
 SG_ S2P_Lmt5_Over_Utank1_14 : 0|16@1+ (0.1,0) [0|6553.5] "V"  PC
 SG_ S2P_Lmt5_Over_Utank2_14 : 16|16@1+ (0.1,0) [0|6553.5] "V"  PC
 SG_ S2P_Lmt5_Over_Utank3_14 : 32|16@1+ (0.1,0) [0|6553.5] "V"  PC
 SG_ S2P_Lmt5_Over_DUtank_14 : 48|16@1+ (0.1,0) [0|6553.5] "V"  PC

BO_ 2416832079 S2P_Lmt5__15: 8 SBMU
 SG_ S2P_Lmt5_Over_Utank1_15 : 0|16@1+ (0.1,0) [0|6553.5] "V"  PC
 SG_ S2P_Lmt5_Over_Utank2_15 : 16|16@1+ (0.1,0) [0|6553.5] "V"  PC
 SG_ S2P_Lmt5_Over_Utank3_15 : 32|16@1+ (0.1,0) [0|6553.5] "V"  PC
 SG_ S2P_Lmt5_Over_DUtank_15 : 48|16@1+ (0.1,0) [0|6553.5] "V"  PC

BO_ 2416832080 S2P_Lmt5__16: 8 SBMU
 SG_ S2P_Lmt5_Over_Utank1_16 : 0|16@1+ (0.1,0) [0|6553.5] "V"  PC
 SG_ S2P_Lmt5_Over_Utank2_16 : 16|16@1+ (0.1,0) [0|6553.5] "V"  PC
 SG_ S2P_Lmt5_Over_Utank3_16 : 32|16@1+ (0.1,0) [0|6553.5] "V"  PC
 SG_ S2P_Lmt5_Over_DUtank_16 : 48|16@1+ (0.1,0) [0|6553.5] "V"  PC

BO_ 2416832081 S2P_Lmt5__17: 8 SBMU
 SG_ S2P_Lmt5_Over_Utank1_17 : 0|16@1+ (0.1,0) [0|6553.5] "V"  PC
 SG_ S2P_Lmt5_Over_Utank2_17 : 16|16@1+ (0.1,0) [0|6553.5] "V"  PC
 SG_ S2P_Lmt5_Over_Utank3_17 : 32|16@1+ (0.1,0) [0|6553.5] "V"  PC
 SG_ S2P_Lmt5_Over_DUtank_17 : 48|16@1+ (0.1,0) [0|6553.5] "V"  PC

BO_ 2416832082 S2P_Lmt5__18: 8 SBMU
 SG_ S2P_Lmt5_Over_Utank1_18 : 0|16@1+ (0.1,0) [0|6553.5] "V"  PC
 SG_ S2P_Lmt5_Over_Utank2_18 : 16|16@1+ (0.1,0) [0|6553.5] "V"  PC
 SG_ S2P_Lmt5_Over_Utank3_18 : 32|16@1+ (0.1,0) [0|6553.5] "V"  PC
 SG_ S2P_Lmt5_Over_DUtank_18 : 48|16@1+ (0.1,0) [0|6553.5] "V"  PC

BO_ 2416832083 S2P_Lmt5__19: 8 SBMU
 SG_ S2P_Lmt5_Over_Utank1_19 : 0|16@1+ (0.1,0) [0|6553.5] "V"  PC
 SG_ S2P_Lmt5_Over_Utank2_19 : 16|16@1+ (0.1,0) [0|6553.5] "V"  PC
 SG_ S2P_Lmt5_Over_Utank3_19 : 32|16@1+ (0.1,0) [0|6553.5] "V"  PC
 SG_ S2P_Lmt5_Over_DUtank_19 : 48|16@1+ (0.1,0) [0|6553.5] "V"  PC

BO_ 2416832084 S2P_Lmt5__20: 8 SBMU
 SG_ S2P_Lmt5_Over_Utank1_20 : 0|16@1+ (0.1,0) [0|6553.5] "V"  PC
 SG_ S2P_Lmt5_Over_Utank2_20 : 16|16@1+ (0.1,0) [0|6553.5] "V"  PC
 SG_ S2P_Lmt5_Over_Utank3_20 : 32|16@1+ (0.1,0) [0|6553.5] "V"  PC
 SG_ S2P_Lmt5_Over_DUtank_20 : 48|16@1+ (0.1,0) [0|6553.5] "V"  PC

BO_ 2416832085 S2P_Lmt5__21: 8 SBMU
 SG_ S2P_Lmt5_Over_Utank1_21 : 0|16@1+ (0.1,0) [0|6553.5] "V"  PC
 SG_ S2P_Lmt5_Over_Utank2_21 : 16|16@1+ (0.1,0) [0|6553.5] "V"  PC
 SG_ S2P_Lmt5_Over_Utank3_21 : 32|16@1+ (0.1,0) [0|6553.5] "V"  PC
 SG_ S2P_Lmt5_Over_DUtank_21 : 48|16@1+ (0.1,0) [0|6553.5] "V"  PC

BO_ 2416832086 S2P_Lmt5__22: 8 SBMU
 SG_ S2P_Lmt5_Over_Utank1_22 : 0|16@1+ (0.1,0) [0|6553.5] "V"  PC
 SG_ S2P_Lmt5_Over_Utank2_22 : 16|16@1+ (0.1,0) [0|6553.5] "V"  PC
 SG_ S2P_Lmt5_Over_Utank3_22 : 32|16@1+ (0.1,0) [0|6553.5] "V"  PC
 SG_ S2P_Lmt5_Over_DUtank_22 : 48|16@1+ (0.1,0) [0|6553.5] "V"  PC

BO_ 2416832087 S2P_Lmt5__23: 8 SBMU
 SG_ S2P_Lmt5_Over_Utank1_23 : 0|16@1+ (0.1,0) [0|6553.5] "V"  PC
 SG_ S2P_Lmt5_Over_Utank2_23 : 16|16@1+ (0.1,0) [0|6553.5] "V"  PC
 SG_ S2P_Lmt5_Over_Utank3_23 : 32|16@1+ (0.1,0) [0|6553.5] "V"  PC
 SG_ S2P_Lmt5_Over_DUtank_23 : 48|16@1+ (0.1,0) [0|6553.5] "V"  PC

BO_ 2416832088 S2P_Lmt5__24: 8 SBMU
 SG_ S2P_Lmt5_Over_Utank1_24 : 0|16@1+ (0.1,0) [0|6553.5] "V"  PC
 SG_ S2P_Lmt5_Over_Utank2_24 : 16|16@1+ (0.1,0) [0|6553.5] "V"  PC
 SG_ S2P_Lmt5_Over_Utank3_24 : 32|16@1+ (0.1,0) [0|6553.5] "V"  PC
 SG_ S2P_Lmt5_Over_DUtank_24 : 48|16@1+ (0.1,0) [0|6553.5] "V"  PC

BO_ 2416832089 S2P_Lmt5__25: 8 SBMU
 SG_ S2P_Lmt5_Over_Utank1_25 : 0|16@1+ (0.1,0) [0|6553.5] "V"  PC
 SG_ S2P_Lmt5_Over_Utank2_25 : 16|16@1+ (0.1,0) [0|6553.5] "V"  PC
 SG_ S2P_Lmt5_Over_Utank3_25 : 32|16@1+ (0.1,0) [0|6553.5] "V"  PC
 SG_ S2P_Lmt5_Over_DUtank_25 : 48|16@1+ (0.1,0) [0|6553.5] "V"  PC

BO_ 2416832090 S2P_Lmt5__26: 8 SBMU
 SG_ S2P_Lmt5_Over_Utank1_26 : 0|16@1+ (0.1,0) [0|6553.5] "V"  PC
 SG_ S2P_Lmt5_Over_Utank2_26 : 16|16@1+ (0.1,0) [0|6553.5] "V"  PC
 SG_ S2P_Lmt5_Over_Utank3_26 : 32|16@1+ (0.1,0) [0|6553.5] "V"  PC
 SG_ S2P_Lmt5_Over_DUtank_26 : 48|16@1+ (0.1,0) [0|6553.5] "V"  PC

BO_ 2416832091 S2P_Lmt5__27: 8 SBMU
 SG_ S2P_Lmt5_Over_Utank1_27 : 0|16@1+ (0.1,0) [0|6553.5] "V"  PC
 SG_ S2P_Lmt5_Over_Utank2_27 : 16|16@1+ (0.1,0) [0|6553.5] "V"  PC
 SG_ S2P_Lmt5_Over_Utank3_27 : 32|16@1+ (0.1,0) [0|6553.5] "V"  PC
 SG_ S2P_Lmt5_Over_DUtank_27 : 48|16@1+ (0.1,0) [0|6553.5] "V"  PC

BO_ 2416832092 S2P_Lmt5__28: 8 SBMU
 SG_ S2P_Lmt5_Over_Utank1_28 : 0|16@1+ (0.1,0) [0|6553.5] "V"  PC
 SG_ S2P_Lmt5_Over_Utank2_28 : 16|16@1+ (0.1,0) [0|6553.5] "V"  PC
 SG_ S2P_Lmt5_Over_Utank3_28 : 32|16@1+ (0.1,0) [0|6553.5] "V"  PC
 SG_ S2P_Lmt5_Over_DUtank_28 : 48|16@1+ (0.1,0) [0|6553.5] "V"  PC

BO_ 2416832093 S2P_Lmt5__29: 8 SBMU
 SG_ S2P_Lmt5_Over_Utank1_29 : 0|16@1+ (0.1,0) [0|6553.5] "V"  PC
 SG_ S2P_Lmt5_Over_Utank2_29 : 16|16@1+ (0.1,0) [0|6553.5] "V"  PC
 SG_ S2P_Lmt5_Over_Utank3_29 : 32|16@1+ (0.1,0) [0|6553.5] "V"  PC
 SG_ S2P_Lmt5_Over_DUtank_29 : 48|16@1+ (0.1,0) [0|6553.5] "V"  PC

BO_ 2416832094 S2P_Lmt5__30: 8 SBMU
 SG_ S2P_Lmt5_Over_Utank1_30 : 0|16@1+ (0.1,0) [0|6553.5] "V"  PC
 SG_ S2P_Lmt5_Over_Utank2_30 : 16|16@1+ (0.1,0) [0|6553.5] "V"  PC
 SG_ S2P_Lmt5_Over_Utank3_30 : 32|16@1+ (0.1,0) [0|6553.5] "V"  PC
 SG_ S2P_Lmt5_Over_DUtank_30 : 48|16@1+ (0.1,0) [0|6553.5] "V"  PC

BO_ 2416832095 S2P_Lmt5__31: 8 SBMU
 SG_ S2P_Lmt5_Over_Utank1_31 : 0|16@1+ (0.1,0) [0|6553.5] "V"  PC
 SG_ S2P_Lmt5_Over_Utank2_31 : 16|16@1+ (0.1,0) [0|6553.5] "V"  PC
 SG_ S2P_Lmt5_Over_Utank3_31 : 32|16@1+ (0.1,0) [0|6553.5] "V"  PC
 SG_ S2P_Lmt5_Over_DUtank_31 : 48|16@1+ (0.1,0) [0|6553.5] "V"  PC

BO_ 2416832096 S2P_Lmt5__32: 8 SBMU
 SG_ S2P_Lmt5_Over_Utank1_32 : 0|16@1+ (0.1,0) [0|6553.5] "V"  PC
 SG_ S2P_Lmt5_Over_Utank2_32 : 16|16@1+ (0.1,0) [0|6553.5] "V"  PC
 SG_ S2P_Lmt5_Over_Utank3_32 : 32|16@1+ (0.1,0) [0|6553.5] "V"  PC
 SG_ S2P_Lmt5_Over_DUtank_32 : 48|16@1+ (0.1,0) [0|6553.5] "V"  PC

BO_ 2416832097 S2P_Lmt5__33: 8 SBMU
 SG_ S2P_Lmt5_Over_Utank1_33 : 0|16@1+ (0.1,0) [0|6553.5] "V"  PC
 SG_ S2P_Lmt5_Over_Utank2_33 : 16|16@1+ (0.1,0) [0|6553.5] "V"  PC
 SG_ S2P_Lmt5_Over_Utank3_33 : 32|16@1+ (0.1,0) [0|6553.5] "V"  PC
 SG_ S2P_Lmt5_Over_DUtank_33 : 48|16@1+ (0.1,0) [0|6553.5] "V"  PC

BO_ 2416832098 S2P_Lmt5__34: 8 SBMU
 SG_ S2P_Lmt5_Over_Utank1_34 : 0|16@1+ (0.1,0) [0|6553.5] "V"  PC
 SG_ S2P_Lmt5_Over_Utank2_34 : 16|16@1+ (0.1,0) [0|6553.5] "V"  PC
 SG_ S2P_Lmt5_Over_Utank3_34 : 32|16@1+ (0.1,0) [0|6553.5] "V"  PC
 SG_ S2P_Lmt5_Over_DUtank_34 : 48|16@1+ (0.1,0) [0|6553.5] "V"  PC

BO_ 2416832099 S2P_Lmt5__35: 8 SBMU
 SG_ S2P_Lmt5_Over_Utank1_35 : 0|16@1+ (0.1,0) [0|6553.5] "V"  PC
 SG_ S2P_Lmt5_Over_Utank2_35 : 16|16@1+ (0.1,0) [0|6553.5] "V"  PC
 SG_ S2P_Lmt5_Over_Utank3_35 : 32|16@1+ (0.1,0) [0|6553.5] "V"  PC
 SG_ S2P_Lmt5_Over_DUtank_35 : 48|16@1+ (0.1,0) [0|6553.5] "V"  PC

BO_ 2416832100 S2P_Lmt5__36: 8 SBMU
 SG_ S2P_Lmt5_Over_Utank1_36 : 0|16@1+ (0.1,0) [0|6553.5] "V"  PC
 SG_ S2P_Lmt5_Over_Utank2_36 : 16|16@1+ (0.1,0) [0|6553.5] "V"  PC
 SG_ S2P_Lmt5_Over_Utank3_36 : 32|16@1+ (0.1,0) [0|6553.5] "V"  PC
 SG_ S2P_Lmt5_Over_DUtank_36 : 48|16@1+ (0.1,0) [0|6553.5] "V"  PC

BO_ 2416832101 S2P_Lmt5__37: 8 SBMU
 SG_ S2P_Lmt5_Over_Utank1_37 : 0|16@1+ (0.1,0) [0|6553.5] "V"  PC
 SG_ S2P_Lmt5_Over_Utank2_37 : 16|16@1+ (0.1,0) [0|6553.5] "V"  PC
 SG_ S2P_Lmt5_Over_Utank3_37 : 32|16@1+ (0.1,0) [0|6553.5] "V"  PC
 SG_ S2P_Lmt5_Over_DUtank_37 : 48|16@1+ (0.1,0) [0|6553.5] "V"  PC

BO_ 2416832102 S2P_Lmt5__38: 8 SBMU
 SG_ S2P_Lmt5_Over_Utank1_38 : 0|16@1+ (0.1,0) [0|6553.5] "V"  PC
 SG_ S2P_Lmt5_Over_Utank2_38 : 16|16@1+ (0.1,0) [0|6553.5] "V"  PC
 SG_ S2P_Lmt5_Over_Utank3_38 : 32|16@1+ (0.1,0) [0|6553.5] "V"  PC
 SG_ S2P_Lmt5_Over_DUtank_38 : 48|16@1+ (0.1,0) [0|6553.5] "V"  PC

BO_ 2416832103 S2P_Lmt5__39: 8 SBMU
 SG_ S2P_Lmt5_Over_Utank1_39 : 0|16@1+ (0.1,0) [0|6553.5] "V"  PC
 SG_ S2P_Lmt5_Over_Utank2_39 : 16|16@1+ (0.1,0) [0|6553.5] "V"  PC
 SG_ S2P_Lmt5_Over_Utank3_39 : 32|16@1+ (0.1,0) [0|6553.5] "V"  PC
 SG_ S2P_Lmt5_Over_DUtank_39 : 48|16@1+ (0.1,0) [0|6553.5] "V"  PC

BO_ 2416832104 S2P_Lmt5__40: 8 SBMU
 SG_ S2P_Lmt5_Over_Utank1_40 : 0|16@1+ (0.1,0) [0|6553.5] "V"  PC
 SG_ S2P_Lmt5_Over_Utank2_40 : 16|16@1+ (0.1,0) [0|6553.5] "V"  PC
 SG_ S2P_Lmt5_Over_Utank3_40 : 32|16@1+ (0.1,0) [0|6553.5] "V"  PC
 SG_ S2P_Lmt5_Over_DUtank_40 : 48|16@1+ (0.1,0) [0|6553.5] "V"  PC

BO_ 2416832105 S2P_Lmt5__41: 8 SBMU
 SG_ S2P_Lmt5_Over_Utank1_41 : 0|16@1+ (0.1,0) [0|6553.5] "V"  PC
 SG_ S2P_Lmt5_Over_Utank2_41 : 16|16@1+ (0.1,0) [0|6553.5] "V"  PC
 SG_ S2P_Lmt5_Over_Utank3_41 : 32|16@1+ (0.1,0) [0|6553.5] "V"  PC
 SG_ S2P_Lmt5_Over_DUtank_41 : 48|16@1+ (0.1,0) [0|6553.5] "V"  PC

BO_ 2416832106 S2P_Lmt5__42: 8 SBMU
 SG_ S2P_Lmt5_Over_Utank1_42 : 0|16@1+ (0.1,0) [0|6553.5] "V"  PC
 SG_ S2P_Lmt5_Over_Utank2_42 : 16|16@1+ (0.1,0) [0|6553.5] "V"  PC
 SG_ S2P_Lmt5_Over_Utank3_42 : 32|16@1+ (0.1,0) [0|6553.5] "V"  PC
 SG_ S2P_Lmt5_Over_DUtank_42 : 48|16@1+ (0.1,0) [0|6553.5] "V"  PC

BO_ 2416832107 S2P_Lmt5__43: 8 SBMU
 SG_ S2P_Lmt5_Over_Utank1_43 : 0|16@1+ (0.1,0) [0|6553.5] "V"  PC
 SG_ S2P_Lmt5_Over_Utank2_43 : 16|16@1+ (0.1,0) [0|6553.5] "V"  PC
 SG_ S2P_Lmt5_Over_Utank3_43 : 32|16@1+ (0.1,0) [0|6553.5] "V"  PC
 SG_ S2P_Lmt5_Over_DUtank_43 : 48|16@1+ (0.1,0) [0|6553.5] "V"  PC

BO_ 2416832108 S2P_Lmt5__44: 8 SBMU
 SG_ S2P_Lmt5_Over_Utank1_44 : 0|16@1+ (0.1,0) [0|6553.5] "V"  PC
 SG_ S2P_Lmt5_Over_Utank2_44 : 16|16@1+ (0.1,0) [0|6553.5] "V"  PC
 SG_ S2P_Lmt5_Over_Utank3_44 : 32|16@1+ (0.1,0) [0|6553.5] "V"  PC
 SG_ S2P_Lmt5_Over_DUtank_44 : 48|16@1+ (0.1,0) [0|6553.5] "V"  PC

BO_ 2416832109 S2P_Lmt5__45: 8 SBMU
 SG_ S2P_Lmt5_Over_Utank1_45 : 0|16@1+ (0.1,0) [0|6553.5] "V"  PC
 SG_ S2P_Lmt5_Over_Utank2_45 : 16|16@1+ (0.1,0) [0|6553.5] "V"  PC
 SG_ S2P_Lmt5_Over_Utank3_45 : 32|16@1+ (0.1,0) [0|6553.5] "V"  PC
 SG_ S2P_Lmt5_Over_DUtank_45 : 48|16@1+ (0.1,0) [0|6553.5] "V"  PC

BO_ 2416832110 S2P_Lmt5__46: 8 SBMU
 SG_ S2P_Lmt5_Over_Utank1_46 : 0|16@1+ (0.1,0) [0|6553.5] "V"  PC
 SG_ S2P_Lmt5_Over_Utank2_46 : 16|16@1+ (0.1,0) [0|6553.5] "V"  PC
 SG_ S2P_Lmt5_Over_Utank3_46 : 32|16@1+ (0.1,0) [0|6553.5] "V"  PC
 SG_ S2P_Lmt5_Over_DUtank_46 : 48|16@1+ (0.1,0) [0|6553.5] "V"  PC

BO_ 2416832111 S2P_Lmt5__47: 8 SBMU
 SG_ S2P_Lmt5_Over_Utank1_47 : 0|16@1+ (0.1,0) [0|6553.5] "V"  PC
 SG_ S2P_Lmt5_Over_Utank2_47 : 16|16@1+ (0.1,0) [0|6553.5] "V"  PC
 SG_ S2P_Lmt5_Over_Utank3_47 : 32|16@1+ (0.1,0) [0|6553.5] "V"  PC
 SG_ S2P_Lmt5_Over_DUtank_47 : 48|16@1+ (0.1,0) [0|6553.5] "V"  PC

BO_ 2416832112 S2P_Lmt5__48: 8 SBMU
 SG_ S2P_Lmt5_Over_Utank1_48 : 0|16@1+ (0.1,0) [0|6553.5] "V"  PC
 SG_ S2P_Lmt5_Over_Utank2_48 : 16|16@1+ (0.1,0) [0|6553.5] "V"  PC
 SG_ S2P_Lmt5_Over_Utank3_48 : 32|16@1+ (0.1,0) [0|6553.5] "V"  PC
 SG_ S2P_Lmt5_Over_DUtank_48 : 48|16@1+ (0.1,0) [0|6553.5] "V"  PC

BO_ 2416832113 S2P_Lmt5__49: 8 SBMU
 SG_ S2P_Lmt5_Over_Utank1_49 : 0|16@1+ (0.1,0) [0|6553.5] "V"  PC
 SG_ S2P_Lmt5_Over_Utank2_49 : 16|16@1+ (0.1,0) [0|6553.5] "V"  PC
 SG_ S2P_Lmt5_Over_Utank3_49 : 32|16@1+ (0.1,0) [0|6553.5] "V"  PC
 SG_ S2P_Lmt5_Over_DUtank_49 : 48|16@1+ (0.1,0) [0|6553.5] "V"  PC

BO_ 2416832114 S2P_Lmt5__50: 8 SBMU
 SG_ S2P_Lmt5_Over_Utank1_50 : 0|16@1+ (0.1,0) [0|6553.5] "V"  PC
 SG_ S2P_Lmt5_Over_Utank2_50 : 16|16@1+ (0.1,0) [0|6553.5] "V"  PC
 SG_ S2P_Lmt5_Over_Utank3_50 : 32|16@1+ (0.1,0) [0|6553.5] "V"  PC
 SG_ S2P_Lmt5_Over_DUtank_50 : 48|16@1+ (0.1,0) [0|6553.5] "V"  PC

BO_ 2416832115 S2P_Lmt5__51: 8 SBMU
 SG_ S2P_Lmt5_Over_Utank1_51 : 0|16@1+ (0.1,0) [0|6553.5] "V"  PC
 SG_ S2P_Lmt5_Over_Utank2_51 : 16|16@1+ (0.1,0) [0|6553.5] "V"  PC
 SG_ S2P_Lmt5_Over_Utank3_51 : 32|16@1+ (0.1,0) [0|6553.5] "V"  PC
 SG_ S2P_Lmt5_Over_DUtank_51 : 48|16@1+ (0.1,0) [0|6553.5] "V"  PC

BO_ 2416832116 S2P_Lmt5__52: 8 SBMU
 SG_ S2P_Lmt5_Over_Utank1_52 : 0|16@1+ (0.1,0) [0|6553.5] "V"  PC
 SG_ S2P_Lmt5_Over_Utank2_52 : 16|16@1+ (0.1,0) [0|6553.5] "V"  PC
 SG_ S2P_Lmt5_Over_Utank3_52 : 32|16@1+ (0.1,0) [0|6553.5] "V"  PC
 SG_ S2P_Lmt5_Over_DUtank_52 : 48|16@1+ (0.1,0) [0|6553.5] "V"  PC

BO_ 2416832117 S2P_Lmt5__53: 8 SBMU
 SG_ S2P_Lmt5_Over_Utank1_53 : 0|16@1+ (0.1,0) [0|6553.5] "V"  PC
 SG_ S2P_Lmt5_Over_Utank2_53 : 16|16@1+ (0.1,0) [0|6553.5] "V"  PC
 SG_ S2P_Lmt5_Over_Utank3_53 : 32|16@1+ (0.1,0) [0|6553.5] "V"  PC
 SG_ S2P_Lmt5_Over_DUtank_53 : 48|16@1+ (0.1,0) [0|6553.5] "V"  PC

BO_ 2416832118 S2P_Lmt5__54: 8 SBMU
 SG_ S2P_Lmt5_Over_Utank1_54 : 0|16@1+ (0.1,0) [0|6553.5] "V"  PC
 SG_ S2P_Lmt5_Over_Utank2_54 : 16|16@1+ (0.1,0) [0|6553.5] "V"  PC
 SG_ S2P_Lmt5_Over_Utank3_54 : 32|16@1+ (0.1,0) [0|6553.5] "V"  PC
 SG_ S2P_Lmt5_Over_DUtank_54 : 48|16@1+ (0.1,0) [0|6553.5] "V"  PC

BO_ 2416832119 S2P_Lmt5__55: 8 SBMU
 SG_ S2P_Lmt5_Over_Utank1_55 : 0|16@1+ (0.1,0) [0|6553.5] "V"  PC
 SG_ S2P_Lmt5_Over_Utank2_55 : 16|16@1+ (0.1,0) [0|6553.5] "V"  PC
 SG_ S2P_Lmt5_Over_Utank3_55 : 32|16@1+ (0.1,0) [0|6553.5] "V"  PC
 SG_ S2P_Lmt5_Over_DUtank_55 : 48|16@1+ (0.1,0) [0|6553.5] "V"  PC

BO_ 2416832120 S2P_Lmt5__56: 8 SBMU
 SG_ S2P_Lmt5_Over_Utank1_56 : 0|16@1+ (0.1,0) [0|6553.5] "V"  PC
 SG_ S2P_Lmt5_Over_Utank2_56 : 16|16@1+ (0.1,0) [0|6553.5] "V"  PC
 SG_ S2P_Lmt5_Over_Utank3_56 : 32|16@1+ (0.1,0) [0|6553.5] "V"  PC
 SG_ S2P_Lmt5_Over_DUtank_56 : 48|16@1+ (0.1,0) [0|6553.5] "V"  PC

BO_ 2416832121 S2P_Lmt5__57: 8 SBMU
 SG_ S2P_Lmt5_Over_Utank1_57 : 0|16@1+ (0.1,0) [0|6553.5] "V"  PC
 SG_ S2P_Lmt5_Over_Utank2_57 : 16|16@1+ (0.1,0) [0|6553.5] "V"  PC
 SG_ S2P_Lmt5_Over_Utank3_57 : 32|16@1+ (0.1,0) [0|6553.5] "V"  PC
 SG_ S2P_Lmt5_Over_DUtank_57 : 48|16@1+ (0.1,0) [0|6553.5] "V"  PC

BO_ 2416832122 S2P_Lmt5__58: 8 SBMU
 SG_ S2P_Lmt5_Over_Utank1_58 : 0|16@1+ (0.1,0) [0|6553.5] "V"  PC
 SG_ S2P_Lmt5_Over_Utank2_58 : 16|16@1+ (0.1,0) [0|6553.5] "V"  PC
 SG_ S2P_Lmt5_Over_Utank3_58 : 32|16@1+ (0.1,0) [0|6553.5] "V"  PC
 SG_ S2P_Lmt5_Over_DUtank_58 : 48|16@1+ (0.1,0) [0|6553.5] "V"  PC

BO_ 2416832123 S2P_Lmt5__59: 8 SBMU
 SG_ S2P_Lmt5_Over_Utank1_59 : 0|16@1+ (0.1,0) [0|6553.5] "V"  PC
 SG_ S2P_Lmt5_Over_Utank2_59 : 16|16@1+ (0.1,0) [0|6553.5] "V"  PC
 SG_ S2P_Lmt5_Over_Utank3_59 : 32|16@1+ (0.1,0) [0|6553.5] "V"  PC
 SG_ S2P_Lmt5_Over_DUtank_59 : 48|16@1+ (0.1,0) [0|6553.5] "V"  PC

BO_ 2416832124 S2P_Lmt5__60: 8 SBMU
 SG_ S2P_Lmt5_Over_Utank1_60 : 0|16@1+ (0.1,0) [0|6553.5] "V"  PC
 SG_ S2P_Lmt5_Over_Utank2_60 : 16|16@1+ (0.1,0) [0|6553.5] "V"  PC
 SG_ S2P_Lmt5_Over_Utank3_60 : 32|16@1+ (0.1,0) [0|6553.5] "V"  PC
 SG_ S2P_Lmt5_Over_DUtank_60 : 48|16@1+ (0.1,0) [0|6553.5] "V"  PC

BO_ 2416832125 S2P_Lmt5__61: 8 SBMU
 SG_ S2P_Lmt5_Over_Utank1_61 : 0|16@1+ (0.1,0) [0|6553.5] "V"  PC
 SG_ S2P_Lmt5_Over_Utank2_61 : 16|16@1+ (0.1,0) [0|6553.5] "V"  PC
 SG_ S2P_Lmt5_Over_Utank3_61 : 32|16@1+ (0.1,0) [0|6553.5] "V"  PC
 SG_ S2P_Lmt5_Over_DUtank_61 : 48|16@1+ (0.1,0) [0|6553.5] "V"  PC

BO_ 2416832126 S2P_Lmt5__62: 8 SBMU
 SG_ S2P_Lmt5_Over_Utank1_62 : 0|16@1+ (0.1,0) [0|6553.5] "V"  PC
 SG_ S2P_Lmt5_Over_Utank2_62 : 16|16@1+ (0.1,0) [0|6553.5] "V"  PC
 SG_ S2P_Lmt5_Over_Utank3_62 : 32|16@1+ (0.1,0) [0|6553.5] "V"  PC
 SG_ S2P_Lmt5_Over_DUtank_62 : 48|16@1+ (0.1,0) [0|6553.5] "V"  PC

BO_ 2416832127 S2P_Lmt5__63: 8 SBMU
 SG_ S2P_Lmt5_Over_Utank1_63 : 0|16@1+ (0.1,0) [0|6553.5] "V"  PC
 SG_ S2P_Lmt5_Over_Utank2_63 : 16|16@1+ (0.1,0) [0|6553.5] "V"  PC
 SG_ S2P_Lmt5_Over_Utank3_63 : 32|16@1+ (0.1,0) [0|6553.5] "V"  PC
 SG_ S2P_Lmt5_Over_DUtank_63 : 48|16@1+ (0.1,0) [0|6553.5] "V"  PC

BO_ 2416897601 S2P_Lmt6__01: 8 SBMU
 SG_ S2P_Lmt6_Under_Utank1_01 : 0|16@1+ (0.1,0) [0|6553.5] "V"  PC
 SG_ S2P_Lmt6_Under_Utank2_01 : 16|16@1+ (0.1,0) [0|6553.5] "V"  PC
 SG_ S2P_Lmt6_Under_Utank3_01 : 32|16@1+ (0.1,0) [0|6553.5] "V"  PC
 SG_ S2P_Lmt6_Under_DUtank_01 : 48|16@1+ (0.1,0) [0|6553.5] "V"  PC

BO_ 2416897602 S2P_Lmt6__02: 8 SBMU
 SG_ S2P_Lmt6_Under_Utank1_02 : 0|16@1+ (0.1,0) [0|6553.5] "V"  PC
 SG_ S2P_Lmt6_Under_Utank2_02 : 16|16@1+ (0.1,0) [0|6553.5] "V"  PC
 SG_ S2P_Lmt6_Under_Utank3_02 : 32|16@1+ (0.1,0) [0|6553.5] "V"  PC
 SG_ S2P_Lmt6_Under_DUtank_02 : 48|16@1+ (0.1,0) [0|6553.5] "V"  PC

BO_ 2416897603 S2P_Lmt6__03: 8 SBMU
 SG_ S2P_Lmt6_Under_Utank1_03 : 0|16@1+ (0.1,0) [0|6553.5] "V"  PC
 SG_ S2P_Lmt6_Under_Utank2_03 : 16|16@1+ (0.1,0) [0|6553.5] "V"  PC
 SG_ S2P_Lmt6_Under_Utank3_03 : 32|16@1+ (0.1,0) [0|6553.5] "V"  PC
 SG_ S2P_Lmt6_Under_DUtank_03 : 48|16@1+ (0.1,0) [0|6553.5] "V"  PC

BO_ 2416897604 S2P_Lmt6__04: 8 SBMU
 SG_ S2P_Lmt6_Under_Utank1_04 : 0|16@1+ (0.1,0) [0|6553.5] "V"  PC
 SG_ S2P_Lmt6_Under_Utank2_04 : 16|16@1+ (0.1,0) [0|6553.5] "V"  PC
 SG_ S2P_Lmt6_Under_Utank3_04 : 32|16@1+ (0.1,0) [0|6553.5] "V"  PC
 SG_ S2P_Lmt6_Under_DUtank_04 : 48|16@1+ (0.1,0) [0|6553.5] "V"  PC

BO_ 2416897605 S2P_Lmt6__05: 8 SBMU
 SG_ S2P_Lmt6_Under_Utank1_05 : 0|16@1+ (0.1,0) [0|6553.5] "V"  PC
 SG_ S2P_Lmt6_Under_Utank2_05 : 16|16@1+ (0.1,0) [0|6553.5] "V"  PC
 SG_ S2P_Lmt6_Under_Utank3_05 : 32|16@1+ (0.1,0) [0|6553.5] "V"  PC
 SG_ S2P_Lmt6_Under_DUtank_05 : 48|16@1+ (0.1,0) [0|6553.5] "V"  PC

BO_ 2416897606 S2P_Lmt6__06: 8 SBMU
 SG_ S2P_Lmt6_Under_Utank1_06 : 0|16@1+ (0.1,0) [0|6553.5] "V"  PC
 SG_ S2P_Lmt6_Under_Utank2_06 : 16|16@1+ (0.1,0) [0|6553.5] "V"  PC
 SG_ S2P_Lmt6_Under_Utank3_06 : 32|16@1+ (0.1,0) [0|6553.5] "V"  PC
 SG_ S2P_Lmt6_Under_DUtank_06 : 48|16@1+ (0.1,0) [0|6553.5] "V"  PC

BO_ 2416897607 S2P_Lmt6__07: 8 SBMU
 SG_ S2P_Lmt6_Under_Utank1_07 : 0|16@1+ (0.1,0) [0|6553.5] "V"  PC
 SG_ S2P_Lmt6_Under_Utank2_07 : 16|16@1+ (0.1,0) [0|6553.5] "V"  PC
 SG_ S2P_Lmt6_Under_Utank3_07 : 32|16@1+ (0.1,0) [0|6553.5] "V"  PC
 SG_ S2P_Lmt6_Under_DUtank_07 : 48|16@1+ (0.1,0) [0|6553.5] "V"  PC

CM_ SG_ 2417749629 S2P_Cfg11_HW_Ver_Byte9_61 "CSC硬件版本号Byte9对应的ASCII码";
CM_ SG_ 2417749629 S2P_Cfg11_HW_Ver_Byte10_61 "CSC硬件版本号Byte10对应的ASCII码";
CM_ SG_ 2417749629 S2P_Cfg11_HW_Ver_Byte11_61 "CSC硬件版本号Byte11对应的ASCII码";
CM_ SG_ 2417749629 S2P_Cfg11_HW_Ver_Byte12_61 "CSC硬件版本号Byte12对应的ASCII码";
CM_ SG_ 2417749629 S2P_Cfg11_HW_Ver_Byte13_61 "CSC硬件版本号Byte13对应的ASCII码";
CM_ SG_ 2417749629 S2P_Cfg11_HW_Ver_Byte14_61 "CSC硬件版本号Byte14对应的ASCII码";
CM_ SG_ 2417749629 S2P_Cfg11_HW_Ver_Byte15_61 "CSC硬件版本号Byte15对应的ASCII码";
CM_ SG_ 2417749629 S2P_Cfg11_HW_Ver_Byte16_61 "CSC硬件版本号最高字节Byte16对应的ASCII码";
CM_ SG_ 2417749630 S2P_Cfg11_HW_Ver_Byte9_62 "CSC硬件版本号Byte9对应的ASCII码";
CM_ SG_ 2417749630 S2P_Cfg11_HW_Ver_Byte10_62 "CSC硬件版本号Byte10对应的ASCII码";
CM_ SG_ 2417749630 S2P_Cfg11_HW_Ver_Byte11_62 "CSC硬件版本号Byte11对应的ASCII码";
CM_ SG_ 2417749630 S2P_Cfg11_HW_Ver_Byte12_62 "CSC硬件版本号Byte12对应的ASCII码";
CM_ SG_ 2417749630 S2P_Cfg11_HW_Ver_Byte13_62 "CSC硬件版本号Byte13对应的ASCII码";
CM_ SG_ 2417749630 S2P_Cfg11_HW_Ver_Byte14_62 "CSC硬件版本号Byte14对应的ASCII码";
CM_ SG_ 2417749630 S2P_Cfg11_HW_Ver_Byte15_62 "CSC硬件版本号Byte15对应的ASCII码";
CM_ SG_ 2417749630 S2P_Cfg11_HW_Ver_Byte16_62 "CSC硬件版本号最高字节Byte16对应的ASCII码";
CM_ SG_ 2417749631 S2P_Cfg11_HW_Ver_Byte9_63 "CSC硬件版本号Byte9对应的ASCII码";
CM_ SG_ 2417749631 S2P_Cfg11_HW_Ver_Byte10_63 "CSC硬件版本号Byte10对应的ASCII码";
CM_ SG_ 2417749631 S2P_Cfg11_HW_Ver_Byte11_63 "CSC硬件版本号Byte11对应的ASCII码";
CM_ SG_ 2417749631 S2P_Cfg11_HW_Ver_Byte12_63 "CSC硬件版本号Byte12对应的ASCII码";
CM_ SG_ 2417749631 S2P_Cfg11_HW_Ver_Byte13_63 "CSC硬件版本号Byte13对应的ASCII码";
CM_ SG_ 2417749631 S2P_Cfg11_HW_Ver_Byte14_63 "CSC硬件版本号Byte14对应的ASCII码";
CM_ SG_ 2417749631 S2P_Cfg11_HW_Ver_Byte15_63 "CSC硬件版本号Byte15对应的ASCII码";
CM_ SG_ 2417749631 S2P_Cfg11_HW_Ver_Byte16_63 "CSC硬件版本号最高字节Byte16对应的ASCII码";
CM_ SG_ 2416569921 S2P_Lmt1_Over_Ucell1_01 "电池单体充电电压一级报警值";
CM_ SG_ 2416569921 S2P_Lmt1_Over_DUcell1_01 "单体过压1级告警消除回差阈值";
CM_ SG_ 2416569921 S2P_Lmt1_Over_Ucell2_01 "电池单体充电电压二级报警值";
CM_ SG_ 2416569921 S2P_Lmt1_Over_DUcell2_01 "单体过压2级告警消除回差阈值";
CM_ SG_ 2416569922 S2P_Lmt1_Over_Ucell1_02 "电池单体充电电压一级报警值";
CM_ SG_ 2416569922 S2P_Lmt1_Over_DUcell1_02 "单体过压1级告警消除回差阈值";
CM_ SG_ 2416569922 S2P_Lmt1_Over_Ucell2_02 "电池单体充电电压二级报警值";
CM_ SG_ 2416569922 S2P_Lmt1_Over_DUcell2_02 "单体过压2级告警消除回差阈值";
CM_ SG_ 2416569923 S2P_Lmt1_Over_Ucell1_03 "电池单体充电电压一级报警值";
CM_ SG_ 2416569923 S2P_Lmt1_Over_DUcell1_03 "单体过压1级告警消除回差阈值";
CM_ SG_ 2416569923 S2P_Lmt1_Over_Ucell2_03 "电池单体充电电压二级报警值";
CM_ SG_ 2416569923 S2P_Lmt1_Over_DUcell2_03 "单体过压2级告警消除回差阈值";
CM_ SG_ 2416569924 S2P_Lmt1_Over_Ucell1_04 "电池单体充电电压一级报警值";
CM_ SG_ 2416569924 S2P_Lmt1_Over_DUcell1_04 "单体过压1级告警消除回差阈值";
CM_ SG_ 2416569924 S2P_Lmt1_Over_Ucell2_04 "电池单体充电电压二级报警值";
CM_ SG_ 2416569924 S2P_Lmt1_Over_DUcell2_04 "单体过压2级告警消除回差阈值";
CM_ SG_ 2416569925 S2P_Lmt1_Over_Ucell1_05 "电池单体充电电压一级报警值";
CM_ SG_ 2416569925 S2P_Lmt1_Over_DUcell1_05 "单体过压1级告警消除回差阈值";
CM_ SG_ 2416569925 S2P_Lmt1_Over_Ucell2_05 "电池单体充电电压二级报警值";
CM_ SG_ 2416569925 S2P_Lmt1_Over_DUcell2_05 "单体过压2级告警消除回差阈值";
CM_ SG_ 2416569926 S2P_Lmt1_Over_Ucell1_06 "电池单体充电电压一级报警值";
CM_ SG_ 2416569926 S2P_Lmt1_Over_DUcell1_06 "单体过压1级告警消除回差阈值";
CM_ SG_ 2416569926 S2P_Lmt1_Over_Ucell2_06 "电池单体充电电压二级报警值";
CM_ SG_ 2416569926 S2P_Lmt1_Over_DUcell2_06 "单体过压2级告警消除回差阈值";
CM_ SG_ 2416569927 S2P_Lmt1_Over_Ucell1_07 "电池单体充电电压一级报警值";
CM_ SG_ 2416569927 S2P_Lmt1_Over_DUcell1_07 "单体过压1级告警消除回差阈值";
CM_ SG_ 2416569927 S2P_Lmt1_Over_Ucell2_07 "电池单体充电电压二级报警值";
CM_ SG_ 2416569927 S2P_Lmt1_Over_DUcell2_07 "单体过压2级告警消除回差阈值";
CM_ SG_ 2416569928 S2P_Lmt1_Over_Ucell1_08 "电池单体充电电压一级报警值";
CM_ SG_ 2416569928 S2P_Lmt1_Over_DUcell1_08 "单体过压1级告警消除回差阈值";
CM_ SG_ 2416569928 S2P_Lmt1_Over_Ucell2_08 "电池单体充电电压二级报警值";
CM_ SG_ 2416569928 S2P_Lmt1_Over_DUcell2_08 "单体过压2级告警消除回差阈值";
CM_ SG_ 2416569929 S2P_Lmt1_Over_Ucell1_09 "电池单体充电电压一级报警值";
CM_ SG_ 2416569929 S2P_Lmt1_Over_DUcell1_09 "单体过压1级告警消除回差阈值";
CM_ SG_ 2416569929 S2P_Lmt1_Over_Ucell2_09 "电池单体充电电压二级报警值";
CM_ SG_ 2416569929 S2P_Lmt1_Over_DUcell2_09 "单体过压2级告警消除回差阈值";
CM_ SG_ 2416569930 S2P_Lmt1_Over_Ucell1_10 "电池单体充电电压一级报警值";
CM_ SG_ 2416569930 S2P_Lmt1_Over_DUcell1_10 "单体过压1级告警消除回差阈值";
CM_ SG_ 2416569930 S2P_Lmt1_Over_Ucell2_10 "电池单体充电电压二级报警值";
CM_ SG_ 2416569930 S2P_Lmt1_Over_DUcell2_10 "单体过压2级告警消除回差阈值";
CM_ SG_ 2416569931 S2P_Lmt1_Over_Ucell1_11 "电池单体充电电压一级报警值";
CM_ SG_ 2416569931 S2P_Lmt1_Over_DUcell1_11 "单体过压1级告警消除回差阈值";
CM_ SG_ 2416569931 S2P_Lmt1_Over_Ucell2_11 "电池单体充电电压二级报警值";
CM_ SG_ 2416569931 S2P_Lmt1_Over_DUcell2_11 "单体过压2级告警消除回差阈值";
CM_ SG_ 2416569932 S2P_Lmt1_Over_Ucell1_12 "电池单体充电电压一级报警值";
CM_ SG_ 2416569932 S2P_Lmt1_Over_DUcell1_12 "单体过压1级告警消除回差阈值";
CM_ SG_ 2416569932 S2P_Lmt1_Over_Ucell2_12 "电池单体充电电压二级报警值";
CM_ SG_ 2416569932 S2P_Lmt1_Over_DUcell2_12 "单体过压2级告警消除回差阈值";
CM_ SG_ 2416569933 S2P_Lmt1_Over_Ucell1_13 "电池单体充电电压一级报警值";
CM_ SG_ 2416569933 S2P_Lmt1_Over_DUcell1_13 "单体过压1级告警消除回差阈值";
CM_ SG_ 2416569933 S2P_Lmt1_Over_Ucell2_13 "电池单体充电电压二级报警值";
CM_ SG_ 2416569933 S2P_Lmt1_Over_DUcell2_13 "单体过压2级告警消除回差阈值";
CM_ SG_ 2416569934 S2P_Lmt1_Over_Ucell1_14 "电池单体充电电压一级报警值";
CM_ SG_ 2416569934 S2P_Lmt1_Over_DUcell1_14 "单体过压1级告警消除回差阈值";
CM_ SG_ 2416569934 S2P_Lmt1_Over_Ucell2_14 "电池单体充电电压二级报警值";
CM_ SG_ 2416569934 S2P_Lmt1_Over_DUcell2_14 "单体过压2级告警消除回差阈值";
CM_ SG_ 2416569935 S2P_Lmt1_Over_Ucell1_15 "电池单体充电电压一级报警值";
CM_ SG_ 2416569935 S2P_Lmt1_Over_DUcell1_15 "单体过压1级告警消除回差阈值";
CM_ SG_ 2416569935 S2P_Lmt1_Over_Ucell2_15 "电池单体充电电压二级报警值";
CM_ SG_ 2416569935 S2P_Lmt1_Over_DUcell2_15 "单体过压2级告警消除回差阈值";
CM_ SG_ 2416569936 S2P_Lmt1_Over_Ucell1_16 "电池单体充电电压一级报警值";
CM_ SG_ 2416569936 S2P_Lmt1_Over_DUcell1_16 "单体过压1级告警消除回差阈值";
CM_ SG_ 2416569936 S2P_Lmt1_Over_Ucell2_16 "电池单体充电电压二级报警值";
CM_ SG_ 2416569936 S2P_Lmt1_Over_DUcell2_16 "单体过压2级告警消除回差阈值";
CM_ SG_ 2416569937 S2P_Lmt1_Over_Ucell1_17 "电池单体充电电压一级报警值";
CM_ SG_ 2416569937 S2P_Lmt1_Over_DUcell1_17 "单体过压1级告警消除回差阈值";
CM_ SG_ 2416569937 S2P_Lmt1_Over_Ucell2_17 "电池单体充电电压二级报警值";
CM_ SG_ 2416569937 S2P_Lmt1_Over_DUcell2_17 "单体过压2级告警消除回差阈值";
CM_ SG_ 2416569938 S2P_Lmt1_Over_Ucell1_18 "电池单体充电电压一级报警值";
CM_ SG_ 2416569938 S2P_Lmt1_Over_DUcell1_18 "单体过压1级告警消除回差阈值";
CM_ SG_ 2416569938 S2P_Lmt1_Over_Ucell2_18 "电池单体充电电压二级报警值";
CM_ SG_ 2416569938 S2P_Lmt1_Over_DUcell2_18 "单体过压2级告警消除回差阈值";
CM_ SG_ 2416569939 S2P_Lmt1_Over_Ucell1_19 "电池单体充电电压一级报警值";
CM_ SG_ 2416569939 S2P_Lmt1_Over_DUcell1_19 "单体过压1级告警消除回差阈值";
CM_ SG_ 2416569939 S2P_Lmt1_Over_Ucell2_19 "电池单体充电电压二级报警值";
CM_ SG_ 2416569939 S2P_Lmt1_Over_DUcell2_19 "单体过压2级告警消除回差阈值";
CM_ SG_ 2416569940 S2P_Lmt1_Over_Ucell1_20 "电池单体充电电压一级报警值";
CM_ SG_ 2416569940 S2P_Lmt1_Over_DUcell1_20 "单体过压1级告警消除回差阈值";
CM_ SG_ 2416569940 S2P_Lmt1_Over_Ucell2_20 "电池单体充电电压二级报警值";
CM_ SG_ 2416569940 S2P_Lmt1_Over_DUcell2_20 "单体过压2级告警消除回差阈值";
CM_ SG_ 2416569941 S2P_Lmt1_Over_Ucell1_21 "电池单体充电电压一级报警值";
CM_ SG_ 2416569941 S2P_Lmt1_Over_DUcell1_21 "单体过压1级告警消除回差阈值";
CM_ SG_ 2416569941 S2P_Lmt1_Over_Ucell2_21 "电池单体充电电压二级报警值";
CM_ SG_ 2416569941 S2P_Lmt1_Over_DUcell2_21 "单体过压2级告警消除回差阈值";
CM_ SG_ 2416569942 S2P_Lmt1_Over_Ucell1_22 "电池单体充电电压一级报警值";
CM_ SG_ 2416569942 S2P_Lmt1_Over_DUcell1_22 "单体过压1级告警消除回差阈值";
CM_ SG_ 2416569942 S2P_Lmt1_Over_Ucell2_22 "电池单体充电电压二级报警值";
CM_ SG_ 2416569942 S2P_Lmt1_Over_DUcell2_22 "单体过压2级告警消除回差阈值";
CM_ SG_ 2416569943 S2P_Lmt1_Over_Ucell1_23 "电池单体充电电压一级报警值";
CM_ SG_ 2416569943 S2P_Lmt1_Over_DUcell1_23 "单体过压1级告警消除回差阈值";
CM_ SG_ 2416569943 S2P_Lmt1_Over_Ucell2_23 "电池单体充电电压二级报警值";
CM_ SG_ 2416569943 S2P_Lmt1_Over_DUcell2_23 "单体过压2级告警消除回差阈值";
CM_ SG_ 2416569944 S2P_Lmt1_Over_Ucell1_24 "电池单体充电电压一级报警值";
CM_ SG_ 2416569944 S2P_Lmt1_Over_DUcell1_24 "单体过压1级告警消除回差阈值";
CM_ SG_ 2416569944 S2P_Lmt1_Over_Ucell2_24 "电池单体充电电压二级报警值";
CM_ SG_ 2416569944 S2P_Lmt1_Over_DUcell2_24 "单体过压2级告警消除回差阈值";
CM_ SG_ 2416569945 S2P_Lmt1_Over_Ucell1_25 "电池单体充电电压一级报警值";
CM_ SG_ 2416569945 S2P_Lmt1_Over_DUcell1_25 "单体过压1级告警消除回差阈值";
CM_ SG_ 2416569945 S2P_Lmt1_Over_Ucell2_25 "电池单体充电电压二级报警值";
CM_ SG_ 2416569945 S2P_Lmt1_Over_DUcell2_25 "单体过压2级告警消除回差阈值";
CM_ SG_ 2416569946 S2P_Lmt1_Over_Ucell1_26 "电池单体充电电压一级报警值";
CM_ SG_ 2416569946 S2P_Lmt1_Over_DUcell1_26 "单体过压1级告警消除回差阈值";
CM_ SG_ 2416569946 S2P_Lmt1_Over_Ucell2_26 "电池单体充电电压二级报警值";
CM_ SG_ 2416569946 S2P_Lmt1_Over_DUcell2_26 "单体过压2级告警消除回差阈值";
CM_ SG_ 2416569947 S2P_Lmt1_Over_Ucell1_27 "电池单体充电电压一级报警值";
CM_ SG_ 2416569947 S2P_Lmt1_Over_DUcell1_27 "单体过压1级告警消除回差阈值";
CM_ SG_ 2416569947 S2P_Lmt1_Over_Ucell2_27 "电池单体充电电压二级报警值";
CM_ SG_ 2416569947 S2P_Lmt1_Over_DUcell2_27 "单体过压2级告警消除回差阈值";
CM_ SG_ 2416569948 S2P_Lmt1_Over_Ucell1_28 "电池单体充电电压一级报警值";
CM_ SG_ 2416569948 S2P_Lmt1_Over_DUcell1_28 "单体过压1级告警消除回差阈值";
CM_ SG_ 2416569948 S2P_Lmt1_Over_Ucell2_28 "电池单体充电电压二级报警值";
CM_ SG_ 2416569948 S2P_Lmt1_Over_DUcell2_28 "单体过压2级告警消除回差阈值";
CM_ SG_ 2416569949 S2P_Lmt1_Over_Ucell1_29 "电池单体充电电压一级报警值";
CM_ SG_ 2416569949 S2P_Lmt1_Over_DUcell1_29 "单体过压1级告警消除回差阈值";
CM_ SG_ 2416569949 S2P_Lmt1_Over_Ucell2_29 "电池单体充电电压二级报警值";
CM_ SG_ 2416569949 S2P_Lmt1_Over_DUcell2_29 "单体过压2级告警消除回差阈值";
CM_ SG_ 2416569950 S2P_Lmt1_Over_Ucell1_30 "电池单体充电电压一级报警值";
CM_ SG_ 2416569950 S2P_Lmt1_Over_DUcell1_30 "单体过压1级告警消除回差阈值";
CM_ SG_ 2416569950 S2P_Lmt1_Over_Ucell2_30 "电池单体充电电压二级报警值";
CM_ SG_ 2416569950 S2P_Lmt1_Over_DUcell2_30 "单体过压2级告警消除回差阈值";
CM_ SG_ 2416569951 S2P_Lmt1_Over_Ucell1_31 "电池单体充电电压一级报警值";
CM_ SG_ 2416569951 S2P_Lmt1_Over_DUcell1_31 "单体过压1级告警消除回差阈值";
CM_ SG_ 2416569951 S2P_Lmt1_Over_Ucell2_31 "电池单体充电电压二级报警值";
CM_ SG_ 2416569951 S2P_Lmt1_Over_DUcell2_31 "单体过压2级告警消除回差阈值";
CM_ SG_ 2416569952 S2P_Lmt1_Over_Ucell1_32 "电池单体充电电压一级报警值";
CM_ SG_ 2416569952 S2P_Lmt1_Over_DUcell1_32 "单体过压1级告警消除回差阈值";
CM_ SG_ 2416569952 S2P_Lmt1_Over_Ucell2_32 "电池单体充电电压二级报警值";
CM_ SG_ 2416569952 S2P_Lmt1_Over_DUcell2_32 "单体过压2级告警消除回差阈值";
CM_ SG_ 2416569953 S2P_Lmt1_Over_Ucell1_33 "电池单体充电电压一级报警值";
CM_ SG_ 2416569953 S2P_Lmt1_Over_DUcell1_33 "单体过压1级告警消除回差阈值";
CM_ SG_ 2416569953 S2P_Lmt1_Over_Ucell2_33 "电池单体充电电压二级报警值";
CM_ SG_ 2416569953 S2P_Lmt1_Over_DUcell2_33 "单体过压2级告警消除回差阈值";
CM_ SG_ 2416569954 S2P_Lmt1_Over_Ucell1_34 "电池单体充电电压一级报警值";
CM_ SG_ 2416569954 S2P_Lmt1_Over_DUcell1_34 "单体过压1级告警消除回差阈值";
CM_ SG_ 2416569954 S2P_Lmt1_Over_Ucell2_34 "电池单体充电电压二级报警值";
CM_ SG_ 2416569954 S2P_Lmt1_Over_DUcell2_34 "单体过压2级告警消除回差阈值";
CM_ SG_ 2416569955 S2P_Lmt1_Over_Ucell1_35 "电池单体充电电压一级报警值";
CM_ SG_ 2416569955 S2P_Lmt1_Over_DUcell1_35 "单体过压1级告警消除回差阈值";
CM_ SG_ 2416569955 S2P_Lmt1_Over_Ucell2_35 "电池单体充电电压二级报警值";
CM_ SG_ 2416569955 S2P_Lmt1_Over_DUcell2_35 "单体过压2级告警消除回差阈值";
CM_ SG_ 2416569956 S2P_Lmt1_Over_Ucell1_36 "电池单体充电电压一级报警值";
CM_ SG_ 2416569956 S2P_Lmt1_Over_DUcell1_36 "单体过压1级告警消除回差阈值";
CM_ SG_ 2416569956 S2P_Lmt1_Over_Ucell2_36 "电池单体充电电压二级报警值";
CM_ SG_ 2416569956 S2P_Lmt1_Over_DUcell2_36 "单体过压2级告警消除回差阈值";
CM_ SG_ 2416569957 S2P_Lmt1_Over_Ucell1_37 "电池单体充电电压一级报警值";
CM_ SG_ 2416569957 S2P_Lmt1_Over_DUcell1_37 "单体过压1级告警消除回差阈值";
CM_ SG_ 2416569957 S2P_Lmt1_Over_Ucell2_37 "电池单体充电电压二级报警值";
CM_ SG_ 2416569957 S2P_Lmt1_Over_DUcell2_37 "单体过压2级告警消除回差阈值";
CM_ SG_ 2416569958 S2P_Lmt1_Over_Ucell1_38 "电池单体充电电压一级报警值";
CM_ SG_ 2416569958 S2P_Lmt1_Over_DUcell1_38 "单体过压1级告警消除回差阈值";
CM_ SG_ 2416569958 S2P_Lmt1_Over_Ucell2_38 "电池单体充电电压二级报警值";
CM_ SG_ 2416569958 S2P_Lmt1_Over_DUcell2_38 "单体过压2级告警消除回差阈值";
CM_ SG_ 2416569959 S2P_Lmt1_Over_Ucell1_39 "电池单体充电电压一级报警值";
CM_ SG_ 2416569959 S2P_Lmt1_Over_DUcell1_39 "单体过压1级告警消除回差阈值";
CM_ SG_ 2416569959 S2P_Lmt1_Over_Ucell2_39 "电池单体充电电压二级报警值";
CM_ SG_ 2416569959 S2P_Lmt1_Over_DUcell2_39 "单体过压2级告警消除回差阈值";
CM_ SG_ 2416569960 S2P_Lmt1_Over_Ucell1_40 "电池单体充电电压一级报警值";
CM_ SG_ 2416569960 S2P_Lmt1_Over_DUcell1_40 "单体过压1级告警消除回差阈值";
CM_ SG_ 2416569960 S2P_Lmt1_Over_Ucell2_40 "电池单体充电电压二级报警值";
CM_ SG_ 2416569960 S2P_Lmt1_Over_DUcell2_40 "单体过压2级告警消除回差阈值";
CM_ SG_ 2416569961 S2P_Lmt1_Over_Ucell1_41 "电池单体充电电压一级报警值";
CM_ SG_ 2416569961 S2P_Lmt1_Over_DUcell1_41 "单体过压1级告警消除回差阈值";
CM_ SG_ 2416569961 S2P_Lmt1_Over_Ucell2_41 "电池单体充电电压二级报警值";
CM_ SG_ 2416569961 S2P_Lmt1_Over_DUcell2_41 "单体过压2级告警消除回差阈值";
CM_ SG_ 2416569962 S2P_Lmt1_Over_Ucell1_42 "电池单体充电电压一级报警值";
CM_ SG_ 2416569962 S2P_Lmt1_Over_DUcell1_42 "单体过压1级告警消除回差阈值";
CM_ SG_ 2416569962 S2P_Lmt1_Over_Ucell2_42 "电池单体充电电压二级报警值";
CM_ SG_ 2416569962 S2P_Lmt1_Over_DUcell2_42 "单体过压2级告警消除回差阈值";
CM_ SG_ 2416569963 S2P_Lmt1_Over_Ucell1_43 "电池单体充电电压一级报警值";
CM_ SG_ 2416569963 S2P_Lmt1_Over_DUcell1_43 "单体过压1级告警消除回差阈值";
CM_ SG_ 2416569963 S2P_Lmt1_Over_Ucell2_43 "电池单体充电电压二级报警值";
CM_ SG_ 2416569963 S2P_Lmt1_Over_DUcell2_43 "单体过压2级告警消除回差阈值";
CM_ SG_ 2416569964 S2P_Lmt1_Over_Ucell1_44 "电池单体充电电压一级报警值";
CM_ SG_ 2416569964 S2P_Lmt1_Over_DUcell1_44 "单体过压1级告警消除回差阈值";
CM_ SG_ 2416569964 S2P_Lmt1_Over_Ucell2_44 "电池单体充电电压二级报警值";
CM_ SG_ 2416569964 S2P_Lmt1_Over_DUcell2_44 "单体过压2级告警消除回差阈值";
CM_ SG_ 2416569965 S2P_Lmt1_Over_Ucell1_45 "电池单体充电电压一级报警值";
CM_ SG_ 2416569965 S2P_Lmt1_Over_DUcell1_45 "单体过压1级告警消除回差阈值";
CM_ SG_ 2416569965 S2P_Lmt1_Over_Ucell2_45 "电池单体充电电压二级报警值";
CM_ SG_ 2416569965 S2P_Lmt1_Over_DUcell2_45 "单体过压2级告警消除回差阈值";
CM_ SG_ 2416569966 S2P_Lmt1_Over_Ucell1_46 "电池单体充电电压一级报警值";
CM_ SG_ 2416569966 S2P_Lmt1_Over_DUcell1_46 "单体过压1级告警消除回差阈值";
CM_ SG_ 2416569966 S2P_Lmt1_Over_Ucell2_46 "电池单体充电电压二级报警值";
CM_ SG_ 2416569966 S2P_Lmt1_Over_DUcell2_46 "单体过压2级告警消除回差阈值";
CM_ SG_ 2416569967 S2P_Lmt1_Over_Ucell1_47 "电池单体充电电压一级报警值";
CM_ SG_ 2416569967 S2P_Lmt1_Over_DUcell1_47 "单体过压1级告警消除回差阈值";
CM_ SG_ 2416569967 S2P_Lmt1_Over_Ucell2_47 "电池单体充电电压二级报警值";
CM_ SG_ 2416569967 S2P_Lmt1_Over_DUcell2_47 "单体过压2级告警消除回差阈值";
CM_ SG_ 2416569968 S2P_Lmt1_Over_Ucell1_48 "电池单体充电电压一级报警值";
CM_ SG_ 2416569968 S2P_Lmt1_Over_DUcell1_48 "单体过压1级告警消除回差阈值";
CM_ SG_ 2416569968 S2P_Lmt1_Over_Ucell2_48 "电池单体充电电压二级报警值";
CM_ SG_ 2416569968 S2P_Lmt1_Over_DUcell2_48 "单体过压2级告警消除回差阈值";
CM_ SG_ 2416569969 S2P_Lmt1_Over_Ucell1_49 "电池单体充电电压一级报警值";
CM_ SG_ 2416569969 S2P_Lmt1_Over_DUcell1_49 "单体过压1级告警消除回差阈值";
CM_ SG_ 2416569969 S2P_Lmt1_Over_Ucell2_49 "电池单体充电电压二级报警值";
CM_ SG_ 2416569969 S2P_Lmt1_Over_DUcell2_49 "单体过压2级告警消除回差阈值";
CM_ SG_ 2416569970 S2P_Lmt1_Over_Ucell1_50 "电池单体充电电压一级报警值";
CM_ SG_ 2416569970 S2P_Lmt1_Over_DUcell1_50 "单体过压1级告警消除回差阈值";
CM_ SG_ 2416569970 S2P_Lmt1_Over_Ucell2_50 "电池单体充电电压二级报警值";
CM_ SG_ 2416569970 S2P_Lmt1_Over_DUcell2_50 "单体过压2级告警消除回差阈值";
CM_ SG_ 2416569971 S2P_Lmt1_Over_Ucell1_51 "电池单体充电电压一级报警值";
CM_ SG_ 2416569971 S2P_Lmt1_Over_DUcell1_51 "单体过压1级告警消除回差阈值";
CM_ SG_ 2416569971 S2P_Lmt1_Over_Ucell2_51 "电池单体充电电压二级报警值";
CM_ SG_ 2416569971 S2P_Lmt1_Over_DUcell2_51 "单体过压2级告警消除回差阈值";
CM_ SG_ 2416569972 S2P_Lmt1_Over_Ucell1_52 "电池单体充电电压一级报警值";
CM_ SG_ 2416569972 S2P_Lmt1_Over_DUcell1_52 "单体过压1级告警消除回差阈值";
CM_ SG_ 2416569972 S2P_Lmt1_Over_Ucell2_52 "电池单体充电电压二级报警值";
CM_ SG_ 2416569972 S2P_Lmt1_Over_DUcell2_52 "单体过压2级告警消除回差阈值";
CM_ SG_ 2416569973 S2P_Lmt1_Over_Ucell1_53 "电池单体充电电压一级报警值";
CM_ SG_ 2416569973 S2P_Lmt1_Over_DUcell1_53 "单体过压1级告警消除回差阈值";
CM_ SG_ 2416569973 S2P_Lmt1_Over_Ucell2_53 "电池单体充电电压二级报警值";
CM_ SG_ 2416569973 S2P_Lmt1_Over_DUcell2_53 "单体过压2级告警消除回差阈值";
CM_ SG_ 2416569974 S2P_Lmt1_Over_Ucell1_54 "电池单体充电电压一级报警值";
CM_ SG_ 2416569974 S2P_Lmt1_Over_DUcell1_54 "单体过压1级告警消除回差阈值";
CM_ SG_ 2416569974 S2P_Lmt1_Over_Ucell2_54 "电池单体充电电压二级报警值";
CM_ SG_ 2416569974 S2P_Lmt1_Over_DUcell2_54 "单体过压2级告警消除回差阈值";
CM_ SG_ 2416569975 S2P_Lmt1_Over_Ucell1_55 "电池单体充电电压一级报警值";
CM_ SG_ 2416569975 S2P_Lmt1_Over_DUcell1_55 "单体过压1级告警消除回差阈值";
CM_ SG_ 2416569975 S2P_Lmt1_Over_Ucell2_55 "电池单体充电电压二级报警值";
CM_ SG_ 2416569975 S2P_Lmt1_Over_DUcell2_55 "单体过压2级告警消除回差阈值";
CM_ SG_ 2416569976 S2P_Lmt1_Over_Ucell1_56 "电池单体充电电压一级报警值";
CM_ SG_ 2416569976 S2P_Lmt1_Over_DUcell1_56 "单体过压1级告警消除回差阈值";
CM_ SG_ 2416569976 S2P_Lmt1_Over_Ucell2_56 "电池单体充电电压二级报警值";
CM_ SG_ 2416569976 S2P_Lmt1_Over_DUcell2_56 "单体过压2级告警消除回差阈值";
CM_ SG_ 2416569977 S2P_Lmt1_Over_Ucell1_57 "电池单体充电电压一级报警值";
CM_ SG_ 2416569977 S2P_Lmt1_Over_DUcell1_57 "单体过压1级告警消除回差阈值";
CM_ SG_ 2416569977 S2P_Lmt1_Over_Ucell2_57 "电池单体充电电压二级报警值";
CM_ SG_ 2416569977 S2P_Lmt1_Over_DUcell2_57 "单体过压2级告警消除回差阈值";
CM_ SG_ 2416569978 S2P_Lmt1_Over_Ucell1_58 "电池单体充电电压一级报警值";
CM_ SG_ 2416569978 S2P_Lmt1_Over_DUcell1_58 "单体过压1级告警消除回差阈值";
CM_ SG_ 2416569978 S2P_Lmt1_Over_Ucell2_58 "电池单体充电电压二级报警值";
CM_ SG_ 2416569978 S2P_Lmt1_Over_DUcell2_58 "单体过压2级告警消除回差阈值";
CM_ SG_ 2416569979 S2P_Lmt1_Over_Ucell1_59 "电池单体充电电压一级报警值";
CM_ SG_ 2416569979 S2P_Lmt1_Over_DUcell1_59 "单体过压1级告警消除回差阈值";
CM_ SG_ 2416569979 S2P_Lmt1_Over_Ucell2_59 "电池单体充电电压二级报警值";
CM_ SG_ 2416569979 S2P_Lmt1_Over_DUcell2_59 "单体过压2级告警消除回差阈值";
CM_ SG_ 2416569980 S2P_Lmt1_Over_Ucell1_60 "电池单体充电电压一级报警值";
CM_ SG_ 2416569980 S2P_Lmt1_Over_DUcell1_60 "单体过压1级告警消除回差阈值";
CM_ SG_ 2416569980 S2P_Lmt1_Over_Ucell2_60 "电池单体充电电压二级报警值";
CM_ SG_ 2416569980 S2P_Lmt1_Over_DUcell2_60 "单体过压2级告警消除回差阈值";
CM_ SG_ 2416569981 S2P_Lmt1_Over_Ucell1_61 "电池单体充电电压一级报警值";
CM_ SG_ 2416569981 S2P_Lmt1_Over_DUcell1_61 "单体过压1级告警消除回差阈值";
CM_ SG_ 2416569981 S2P_Lmt1_Over_Ucell2_61 "电池单体充电电压二级报警值";
CM_ SG_ 2416569981 S2P_Lmt1_Over_DUcell2_61 "单体过压2级告警消除回差阈值";
CM_ SG_ 2416569982 S2P_Lmt1_Over_Ucell1_62 "电池单体充电电压一级报警值";
CM_ SG_ 2416569982 S2P_Lmt1_Over_DUcell1_62 "单体过压1级告警消除回差阈值";
CM_ SG_ 2416569982 S2P_Lmt1_Over_Ucell2_62 "电池单体充电电压二级报警值";
CM_ SG_ 2416569982 S2P_Lmt1_Over_DUcell2_62 "单体过压2级告警消除回差阈值";
CM_ SG_ 2416569983 S2P_Lmt1_Over_Ucell1_63 "电池单体充电电压一级报警值";
CM_ SG_ 2416569983 S2P_Lmt1_Over_DUcell1_63 "单体过压1级告警消除回差阈值";
CM_ SG_ 2416569983 S2P_Lmt1_Over_Ucell2_63 "电池单体充电电压二级报警值";
CM_ SG_ 2416569983 S2P_Lmt1_Over_DUcell2_63 "单体过压2级告警消除回差阈值";
CM_ SG_ 2416635457 S2P_Lmt2_Under_Ucell1_01 "电池单体放电电压一级报警值";
CM_ SG_ 2416635457 S2P_Lmt2_Under_DUcell1_01 "单体欠压1级告警消除回差阈值";
CM_ SG_ 2416635457 S2P_Lmt2_Under_Ucell2_01 "电池单体放电电压二级报警值";
CM_ SG_ 2416635457 S2P_Lmt2_Under_DUcell2_01 "单体欠压2级告警消除回差阈值";
CM_ SG_ 2416635458 S2P_Lmt2_Under_Ucell1_02 "电池单体放电电压一级报警值";
CM_ SG_ 2416635458 S2P_Lmt2_Under_DUcell1_02 "单体欠压1级告警消除回差阈值";
CM_ SG_ 2416635458 S2P_Lmt2_Under_Ucell2_02 "电池单体放电电压二级报警值";
CM_ SG_ 2416635458 S2P_Lmt2_Under_DUcell2_02 "单体欠压2级告警消除回差阈值";
CM_ SG_ 2416635459 S2P_Lmt2_Under_Ucell1_03 "电池单体放电电压一级报警值";
CM_ SG_ 2416635459 S2P_Lmt2_Under_DUcell1_03 "单体欠压1级告警消除回差阈值";
CM_ SG_ 2416635459 S2P_Lmt2_Under_Ucell2_03 "电池单体放电电压二级报警值";
CM_ SG_ 2416635459 S2P_Lmt2_Under_DUcell2_03 "单体欠压2级告警消除回差阈值";
CM_ SG_ 2416635460 S2P_Lmt2_Under_Ucell1_04 "电池单体放电电压一级报警值";
CM_ SG_ 2416635460 S2P_Lmt2_Under_DUcell1_04 "单体欠压1级告警消除回差阈值";
CM_ SG_ 2416635460 S2P_Lmt2_Under_Ucell2_04 "电池单体放电电压二级报警值";
CM_ SG_ 2416635460 S2P_Lmt2_Under_DUcell2_04 "单体欠压2级告警消除回差阈值";
CM_ SG_ 2416635461 S2P_Lmt2_Under_Ucell1_05 "电池单体放电电压一级报警值";
CM_ SG_ 2416635461 S2P_Lmt2_Under_DUcell1_05 "单体欠压1级告警消除回差阈值";
CM_ SG_ 2416635461 S2P_Lmt2_Under_Ucell2_05 "电池单体放电电压二级报警值";
CM_ SG_ 2416635461 S2P_Lmt2_Under_DUcell2_05 "单体欠压2级告警消除回差阈值";
CM_ SG_ 2416635462 S2P_Lmt2_Under_Ucell1_06 "电池单体放电电压一级报警值";
CM_ SG_ 2416635462 S2P_Lmt2_Under_DUcell1_06 "单体欠压1级告警消除回差阈值";
CM_ SG_ 2416635462 S2P_Lmt2_Under_Ucell2_06 "电池单体放电电压二级报警值";
CM_ SG_ 2416635462 S2P_Lmt2_Under_DUcell2_06 "单体欠压2级告警消除回差阈值";
CM_ SG_ 2416635463 S2P_Lmt2_Under_Ucell1_07 "电池单体放电电压一级报警值";
CM_ SG_ 2416635463 S2P_Lmt2_Under_DUcell1_07 "单体欠压1级告警消除回差阈值";
CM_ SG_ 2416635463 S2P_Lmt2_Under_Ucell2_07 "电池单体放电电压二级报警值";
CM_ SG_ 2416635463 S2P_Lmt2_Under_DUcell2_07 "单体欠压2级告警消除回差阈值";
CM_ SG_ 2416635464 S2P_Lmt2_Under_Ucell1_08 "电池单体放电电压一级报警值";
CM_ SG_ 2416635464 S2P_Lmt2_Under_DUcell1_08 "单体欠压1级告警消除回差阈值";
CM_ SG_ 2416635464 S2P_Lmt2_Under_Ucell2_08 "电池单体放电电压二级报警值";
CM_ SG_ 2416635464 S2P_Lmt2_Under_DUcell2_08 "单体欠压2级告警消除回差阈值";
CM_ SG_ 2416635465 S2P_Lmt2_Under_Ucell1_09 "电池单体放电电压一级报警值";
CM_ SG_ 2416635465 S2P_Lmt2_Under_DUcell1_09 "单体欠压1级告警消除回差阈值";
CM_ SG_ 2416635465 S2P_Lmt2_Under_Ucell2_09 "电池单体放电电压二级报警值";
CM_ SG_ 2416635465 S2P_Lmt2_Under_DUcell2_09 "单体欠压2级告警消除回差阈值";
CM_ SG_ 2416635466 S2P_Lmt2_Under_Ucell1_10 "电池单体放电电压一级报警值";
CM_ SG_ 2416635466 S2P_Lmt2_Under_DUcell1_10 "单体欠压1级告警消除回差阈值";
CM_ SG_ 2416635466 S2P_Lmt2_Under_Ucell2_10 "电池单体放电电压二级报警值";
CM_ SG_ 2416635466 S2P_Lmt2_Under_DUcell2_10 "单体欠压2级告警消除回差阈值";
CM_ SG_ 2416635467 S2P_Lmt2_Under_Ucell1_11 "电池单体放电电压一级报警值";
CM_ SG_ 2416635467 S2P_Lmt2_Under_DUcell1_11 "单体欠压1级告警消除回差阈值";
CM_ SG_ 2416635467 S2P_Lmt2_Under_Ucell2_11 "电池单体放电电压二级报警值";
CM_ SG_ 2416635467 S2P_Lmt2_Under_DUcell2_11 "单体欠压2级告警消除回差阈值";
CM_ SG_ 2416635468 S2P_Lmt2_Under_Ucell1_12 "电池单体放电电压一级报警值";
CM_ SG_ 2416635468 S2P_Lmt2_Under_DUcell1_12 "单体欠压1级告警消除回差阈值";
CM_ SG_ 2416635468 S2P_Lmt2_Under_Ucell2_12 "电池单体放电电压二级报警值";
CM_ SG_ 2416635468 S2P_Lmt2_Under_DUcell2_12 "单体欠压2级告警消除回差阈值";
CM_ SG_ 2416635469 S2P_Lmt2_Under_Ucell1_13 "电池单体放电电压一级报警值";
CM_ SG_ 2416635469 S2P_Lmt2_Under_DUcell1_13 "单体欠压1级告警消除回差阈值";
CM_ SG_ 2416635469 S2P_Lmt2_Under_Ucell2_13 "电池单体放电电压二级报警值";
CM_ SG_ 2416635469 S2P_Lmt2_Under_DUcell2_13 "单体欠压2级告警消除回差阈值";
CM_ SG_ 2416635470 S2P_Lmt2_Under_Ucell1_14 "电池单体放电电压一级报警值";
CM_ SG_ 2416635470 S2P_Lmt2_Under_DUcell1_14 "单体欠压1级告警消除回差阈值";
CM_ SG_ 2416635470 S2P_Lmt2_Under_Ucell2_14 "电池单体放电电压二级报警值";
CM_ SG_ 2416635470 S2P_Lmt2_Under_DUcell2_14 "单体欠压2级告警消除回差阈值";
CM_ SG_ 2416635471 S2P_Lmt2_Under_Ucell1_15 "电池单体放电电压一级报警值";
CM_ SG_ 2416635471 S2P_Lmt2_Under_DUcell1_15 "单体欠压1级告警消除回差阈值";
CM_ SG_ 2416635471 S2P_Lmt2_Under_Ucell2_15 "电池单体放电电压二级报警值";
CM_ SG_ 2416635471 S2P_Lmt2_Under_DUcell2_15 "单体欠压2级告警消除回差阈值";
CM_ SG_ 2416635472 S2P_Lmt2_Under_Ucell1_16 "电池单体放电电压一级报警值";
CM_ SG_ 2416635472 S2P_Lmt2_Under_DUcell1_16 "单体欠压1级告警消除回差阈值";
CM_ SG_ 2416635472 S2P_Lmt2_Under_Ucell2_16 "电池单体放电电压二级报警值";
CM_ SG_ 2416635472 S2P_Lmt2_Under_DUcell2_16 "单体欠压2级告警消除回差阈值";
CM_ SG_ 2416635473 S2P_Lmt2_Under_Ucell1_17 "电池单体放电电压一级报警值";
CM_ SG_ 2416635473 S2P_Lmt2_Under_DUcell1_17 "单体欠压1级告警消除回差阈值";
CM_ SG_ 2416635473 S2P_Lmt2_Under_Ucell2_17 "电池单体放电电压二级报警值";
CM_ SG_ 2416635473 S2P_Lmt2_Under_DUcell2_17 "单体欠压2级告警消除回差阈值";
CM_ SG_ 2416635474 S2P_Lmt2_Under_Ucell1_18 "电池单体放电电压一级报警值";
CM_ SG_ 2416635474 S2P_Lmt2_Under_DUcell1_18 "单体欠压1级告警消除回差阈值";
CM_ SG_ 2416635474 S2P_Lmt2_Under_Ucell2_18 "电池单体放电电压二级报警值";
CM_ SG_ 2416635474 S2P_Lmt2_Under_DUcell2_18 "单体欠压2级告警消除回差阈值";
CM_ SG_ 2416635475 S2P_Lmt2_Under_Ucell1_19 "电池单体放电电压一级报警值";
CM_ SG_ 2416635475 S2P_Lmt2_Under_DUcell1_19 "单体欠压1级告警消除回差阈值";
CM_ SG_ 2416635475 S2P_Lmt2_Under_Ucell2_19 "电池单体放电电压二级报警值";
CM_ SG_ 2416635475 S2P_Lmt2_Under_DUcell2_19 "单体欠压2级告警消除回差阈值";
CM_ SG_ 2416635476 S2P_Lmt2_Under_Ucell1_20 "电池单体放电电压一级报警值";
CM_ SG_ 2416635476 S2P_Lmt2_Under_DUcell1_20 "单体欠压1级告警消除回差阈值";
CM_ SG_ 2416635476 S2P_Lmt2_Under_Ucell2_20 "电池单体放电电压二级报警值";
CM_ SG_ 2416635476 S2P_Lmt2_Under_DUcell2_20 "单体欠压2级告警消除回差阈值";
CM_ SG_ 2416635477 S2P_Lmt2_Under_Ucell1_21 "电池单体放电电压一级报警值";
CM_ SG_ 2416635477 S2P_Lmt2_Under_DUcell1_21 "单体欠压1级告警消除回差阈值";
CM_ SG_ 2416635477 S2P_Lmt2_Under_Ucell2_21 "电池单体放电电压二级报警值";
CM_ SG_ 2416635477 S2P_Lmt2_Under_DUcell2_21 "单体欠压2级告警消除回差阈值";
CM_ SG_ 2416635478 S2P_Lmt2_Under_Ucell1_22 "电池单体放电电压一级报警值";
CM_ SG_ 2416635478 S2P_Lmt2_Under_DUcell1_22 "单体欠压1级告警消除回差阈值";
CM_ SG_ 2416635478 S2P_Lmt2_Under_Ucell2_22 "电池单体放电电压二级报警值";
CM_ SG_ 2416635478 S2P_Lmt2_Under_DUcell2_22 "单体欠压2级告警消除回差阈值";
CM_ SG_ 2416635479 S2P_Lmt2_Under_Ucell1_23 "电池单体放电电压一级报警值";
CM_ SG_ 2416635479 S2P_Lmt2_Under_DUcell1_23 "单体欠压1级告警消除回差阈值";
CM_ SG_ 2416635479 S2P_Lmt2_Under_Ucell2_23 "电池单体放电电压二级报警值";
CM_ SG_ 2416635479 S2P_Lmt2_Under_DUcell2_23 "单体欠压2级告警消除回差阈值";
CM_ SG_ 2416635480 S2P_Lmt2_Under_Ucell1_24 "电池单体放电电压一级报警值";
CM_ SG_ 2416635480 S2P_Lmt2_Under_DUcell1_24 "单体欠压1级告警消除回差阈值";
CM_ SG_ 2416635480 S2P_Lmt2_Under_Ucell2_24 "电池单体放电电压二级报警值";
CM_ SG_ 2416635480 S2P_Lmt2_Under_DUcell2_24 "单体欠压2级告警消除回差阈值";
CM_ SG_ 2416635481 S2P_Lmt2_Under_Ucell1_25 "电池单体放电电压一级报警值";
CM_ SG_ 2416635481 S2P_Lmt2_Under_DUcell1_25 "单体欠压1级告警消除回差阈值";
CM_ SG_ 2416635481 S2P_Lmt2_Under_Ucell2_25 "电池单体放电电压二级报警值";
CM_ SG_ 2416635481 S2P_Lmt2_Under_DUcell2_25 "单体欠压2级告警消除回差阈值";
CM_ SG_ 2416635482 S2P_Lmt2_Under_Ucell1_26 "电池单体放电电压一级报警值";
CM_ SG_ 2416635482 S2P_Lmt2_Under_DUcell1_26 "单体欠压1级告警消除回差阈值";
CM_ SG_ 2416635482 S2P_Lmt2_Under_Ucell2_26 "电池单体放电电压二级报警值";
CM_ SG_ 2416635482 S2P_Lmt2_Under_DUcell2_26 "单体欠压2级告警消除回差阈值";
CM_ SG_ 2416635483 S2P_Lmt2_Under_Ucell1_27 "电池单体放电电压一级报警值";
CM_ SG_ 2416635483 S2P_Lmt2_Under_DUcell1_27 "单体欠压1级告警消除回差阈值";
CM_ SG_ 2416635483 S2P_Lmt2_Under_Ucell2_27 "电池单体放电电压二级报警值";
CM_ SG_ 2416635483 S2P_Lmt2_Under_DUcell2_27 "单体欠压2级告警消除回差阈值";
CM_ SG_ 2416635484 S2P_Lmt2_Under_Ucell1_28 "电池单体放电电压一级报警值";
CM_ SG_ 2416635484 S2P_Lmt2_Under_DUcell1_28 "单体欠压1级告警消除回差阈值";
CM_ SG_ 2416635484 S2P_Lmt2_Under_Ucell2_28 "电池单体放电电压二级报警值";
CM_ SG_ 2416635484 S2P_Lmt2_Under_DUcell2_28 "单体欠压2级告警消除回差阈值";
CM_ SG_ 2416635485 S2P_Lmt2_Under_Ucell1_29 "电池单体放电电压一级报警值";
CM_ SG_ 2416635485 S2P_Lmt2_Under_DUcell1_29 "单体欠压1级告警消除回差阈值";
CM_ SG_ 2416635485 S2P_Lmt2_Under_Ucell2_29 "电池单体放电电压二级报警值";
CM_ SG_ 2416635485 S2P_Lmt2_Under_DUcell2_29 "单体欠压2级告警消除回差阈值";
CM_ SG_ 2416635486 S2P_Lmt2_Under_Ucell1_30 "电池单体放电电压一级报警值";
CM_ SG_ 2416635486 S2P_Lmt2_Under_DUcell1_30 "单体欠压1级告警消除回差阈值";
CM_ SG_ 2416635486 S2P_Lmt2_Under_Ucell2_30 "电池单体放电电压二级报警值";
CM_ SG_ 2416635486 S2P_Lmt2_Under_DUcell2_30 "单体欠压2级告警消除回差阈值";
CM_ SG_ 2416635487 S2P_Lmt2_Under_Ucell1_31 "电池单体放电电压一级报警值";
CM_ SG_ 2416635487 S2P_Lmt2_Under_DUcell1_31 "单体欠压1级告警消除回差阈值";
CM_ SG_ 2416635487 S2P_Lmt2_Under_Ucell2_31 "电池单体放电电压二级报警值";
CM_ SG_ 2416635487 S2P_Lmt2_Under_DUcell2_31 "单体欠压2级告警消除回差阈值";
CM_ SG_ 2416635488 S2P_Lmt2_Under_Ucell1_32 "电池单体放电电压一级报警值";
CM_ SG_ 2416635488 S2P_Lmt2_Under_DUcell1_32 "单体欠压1级告警消除回差阈值";
CM_ SG_ 2416635488 S2P_Lmt2_Under_Ucell2_32 "电池单体放电电压二级报警值";
CM_ SG_ 2416635488 S2P_Lmt2_Under_DUcell2_32 "单体欠压2级告警消除回差阈值";
CM_ SG_ 2416635489 S2P_Lmt2_Under_Ucell1_33 "电池单体放电电压一级报警值";
CM_ SG_ 2416635489 S2P_Lmt2_Under_DUcell1_33 "单体欠压1级告警消除回差阈值";
CM_ SG_ 2416635489 S2P_Lmt2_Under_Ucell2_33 "电池单体放电电压二级报警值";
CM_ SG_ 2416635489 S2P_Lmt2_Under_DUcell2_33 "单体欠压2级告警消除回差阈值";
CM_ SG_ 2416635490 S2P_Lmt2_Under_Ucell1_34 "电池单体放电电压一级报警值";
CM_ SG_ 2416635490 S2P_Lmt2_Under_DUcell1_34 "单体欠压1级告警消除回差阈值";
CM_ SG_ 2416635490 S2P_Lmt2_Under_Ucell2_34 "电池单体放电电压二级报警值";
CM_ SG_ 2416635490 S2P_Lmt2_Under_DUcell2_34 "单体欠压2级告警消除回差阈值";
CM_ SG_ 2416635491 S2P_Lmt2_Under_Ucell1_35 "电池单体放电电压一级报警值";
CM_ SG_ 2416635491 S2P_Lmt2_Under_DUcell1_35 "单体欠压1级告警消除回差阈值";
CM_ SG_ 2416635491 S2P_Lmt2_Under_Ucell2_35 "电池单体放电电压二级报警值";
CM_ SG_ 2416635491 S2P_Lmt2_Under_DUcell2_35 "单体欠压2级告警消除回差阈值";
CM_ SG_ 2416635492 S2P_Lmt2_Under_Ucell1_36 "电池单体放电电压一级报警值";
CM_ SG_ 2416635492 S2P_Lmt2_Under_DUcell1_36 "单体欠压1级告警消除回差阈值";
CM_ SG_ 2416635492 S2P_Lmt2_Under_Ucell2_36 "电池单体放电电压二级报警值";
CM_ SG_ 2416635492 S2P_Lmt2_Under_DUcell2_36 "单体欠压2级告警消除回差阈值";
CM_ SG_ 2416635493 S2P_Lmt2_Under_Ucell1_37 "电池单体放电电压一级报警值";
CM_ SG_ 2416635493 S2P_Lmt2_Under_DUcell1_37 "单体欠压1级告警消除回差阈值";
CM_ SG_ 2416635493 S2P_Lmt2_Under_Ucell2_37 "电池单体放电电压二级报警值";
CM_ SG_ 2416635493 S2P_Lmt2_Under_DUcell2_37 "单体欠压2级告警消除回差阈值";
CM_ SG_ 2416635494 S2P_Lmt2_Under_Ucell1_38 "电池单体放电电压一级报警值";
CM_ SG_ 2416635494 S2P_Lmt2_Under_DUcell1_38 "单体欠压1级告警消除回差阈值";
CM_ SG_ 2416635494 S2P_Lmt2_Under_Ucell2_38 "电池单体放电电压二级报警值";
CM_ SG_ 2416635494 S2P_Lmt2_Under_DUcell2_38 "单体欠压2级告警消除回差阈值";
CM_ SG_ 2416635495 S2P_Lmt2_Under_Ucell1_39 "电池单体放电电压一级报警值";
CM_ SG_ 2416635495 S2P_Lmt2_Under_DUcell1_39 "单体欠压1级告警消除回差阈值";
CM_ SG_ 2416635495 S2P_Lmt2_Under_Ucell2_39 "电池单体放电电压二级报警值";
CM_ SG_ 2416635495 S2P_Lmt2_Under_DUcell2_39 "单体欠压2级告警消除回差阈值";
CM_ SG_ 2416635496 S2P_Lmt2_Under_Ucell1_40 "电池单体放电电压一级报警值";
CM_ SG_ 2416635496 S2P_Lmt2_Under_DUcell1_40 "单体欠压1级告警消除回差阈值";
CM_ SG_ 2416635496 S2P_Lmt2_Under_Ucell2_40 "电池单体放电电压二级报警值";
CM_ SG_ 2416635496 S2P_Lmt2_Under_DUcell2_40 "单体欠压2级告警消除回差阈值";
CM_ SG_ 2416635497 S2P_Lmt2_Under_Ucell1_41 "电池单体放电电压一级报警值";
CM_ SG_ 2416635497 S2P_Lmt2_Under_DUcell1_41 "单体欠压1级告警消除回差阈值";
CM_ SG_ 2416635497 S2P_Lmt2_Under_Ucell2_41 "电池单体放电电压二级报警值";
CM_ SG_ 2416635497 S2P_Lmt2_Under_DUcell2_41 "单体欠压2级告警消除回差阈值";
CM_ SG_ 2416635498 S2P_Lmt2_Under_Ucell1_42 "电池单体放电电压一级报警值";
CM_ SG_ 2416635498 S2P_Lmt2_Under_DUcell1_42 "单体欠压1级告警消除回差阈值";
CM_ SG_ 2416635498 S2P_Lmt2_Under_Ucell2_42 "电池单体放电电压二级报警值";
CM_ SG_ 2416635498 S2P_Lmt2_Under_DUcell2_42 "单体欠压2级告警消除回差阈值";
CM_ SG_ 2416635499 S2P_Lmt2_Under_Ucell1_43 "电池单体放电电压一级报警值";
CM_ SG_ 2416635499 S2P_Lmt2_Under_DUcell1_43 "单体欠压1级告警消除回差阈值";
CM_ SG_ 2416635499 S2P_Lmt2_Under_Ucell2_43 "电池单体放电电压二级报警值";
CM_ SG_ 2416635499 S2P_Lmt2_Under_DUcell2_43 "单体欠压2级告警消除回差阈值";
CM_ SG_ 2416635500 S2P_Lmt2_Under_Ucell1_44 "电池单体放电电压一级报警值";
CM_ SG_ 2416635500 S2P_Lmt2_Under_DUcell1_44 "单体欠压1级告警消除回差阈值";
CM_ SG_ 2416635500 S2P_Lmt2_Under_Ucell2_44 "电池单体放电电压二级报警值";
CM_ SG_ 2416635500 S2P_Lmt2_Under_DUcell2_44 "单体欠压2级告警消除回差阈值";
CM_ SG_ 2416635501 S2P_Lmt2_Under_Ucell1_45 "电池单体放电电压一级报警值";
CM_ SG_ 2416635501 S2P_Lmt2_Under_DUcell1_45 "单体欠压1级告警消除回差阈值";
CM_ SG_ 2416635501 S2P_Lmt2_Under_Ucell2_45 "电池单体放电电压二级报警值";
CM_ SG_ 2416635501 S2P_Lmt2_Under_DUcell2_45 "单体欠压2级告警消除回差阈值";
CM_ SG_ 2416635502 S2P_Lmt2_Under_Ucell1_46 "电池单体放电电压一级报警值";
CM_ SG_ 2416635502 S2P_Lmt2_Under_DUcell1_46 "单体欠压1级告警消除回差阈值";
CM_ SG_ 2416635502 S2P_Lmt2_Under_Ucell2_46 "电池单体放电电压二级报警值";
CM_ SG_ 2416635502 S2P_Lmt2_Under_DUcell2_46 "单体欠压2级告警消除回差阈值";
CM_ SG_ 2416635503 S2P_Lmt2_Under_Ucell1_47 "电池单体放电电压一级报警值";
CM_ SG_ 2416635503 S2P_Lmt2_Under_DUcell1_47 "单体欠压1级告警消除回差阈值";
CM_ SG_ 2416635503 S2P_Lmt2_Under_Ucell2_47 "电池单体放电电压二级报警值";
CM_ SG_ 2416635503 S2P_Lmt2_Under_DUcell2_47 "单体欠压2级告警消除回差阈值";
CM_ SG_ 2416635504 S2P_Lmt2_Under_Ucell1_48 "电池单体放电电压一级报警值";
CM_ SG_ 2416635504 S2P_Lmt2_Under_DUcell1_48 "单体欠压1级告警消除回差阈值";
CM_ SG_ 2416635504 S2P_Lmt2_Under_Ucell2_48 "电池单体放电电压二级报警值";
CM_ SG_ 2416635504 S2P_Lmt2_Under_DUcell2_48 "单体欠压2级告警消除回差阈值";
CM_ SG_ 2416635505 S2P_Lmt2_Under_Ucell1_49 "电池单体放电电压一级报警值";
CM_ SG_ 2416635505 S2P_Lmt2_Under_DUcell1_49 "单体欠压1级告警消除回差阈值";
CM_ SG_ 2416635505 S2P_Lmt2_Under_Ucell2_49 "电池单体放电电压二级报警值";
CM_ SG_ 2416635505 S2P_Lmt2_Under_DUcell2_49 "单体欠压2级告警消除回差阈值";
CM_ SG_ 2416635506 S2P_Lmt2_Under_Ucell1_50 "电池单体放电电压一级报警值";
CM_ SG_ 2416635506 S2P_Lmt2_Under_DUcell1_50 "单体欠压1级告警消除回差阈值";
CM_ SG_ 2416635506 S2P_Lmt2_Under_Ucell2_50 "电池单体放电电压二级报警值";
CM_ SG_ 2416635506 S2P_Lmt2_Under_DUcell2_50 "单体欠压2级告警消除回差阈值";
CM_ SG_ 2416635507 S2P_Lmt2_Under_Ucell1_51 "电池单体放电电压一级报警值";
CM_ SG_ 2416635507 S2P_Lmt2_Under_DUcell1_51 "单体欠压1级告警消除回差阈值";
CM_ SG_ 2416635507 S2P_Lmt2_Under_Ucell2_51 "电池单体放电电压二级报警值";
CM_ SG_ 2416635507 S2P_Lmt2_Under_DUcell2_51 "单体欠压2级告警消除回差阈值";
CM_ SG_ 2416635508 S2P_Lmt2_Under_Ucell1_52 "电池单体放电电压一级报警值";
CM_ SG_ 2416635508 S2P_Lmt2_Under_DUcell1_52 "单体欠压1级告警消除回差阈值";
CM_ SG_ 2416635508 S2P_Lmt2_Under_Ucell2_52 "电池单体放电电压二级报警值";
CM_ SG_ 2416635508 S2P_Lmt2_Under_DUcell2_52 "单体欠压2级告警消除回差阈值";
CM_ SG_ 2416635509 S2P_Lmt2_Under_Ucell1_53 "电池单体放电电压一级报警值";
CM_ SG_ 2416635509 S2P_Lmt2_Under_DUcell1_53 "单体欠压1级告警消除回差阈值";
CM_ SG_ 2416635509 S2P_Lmt2_Under_Ucell2_53 "电池单体放电电压二级报警值";
CM_ SG_ 2416635509 S2P_Lmt2_Under_DUcell2_53 "单体欠压2级告警消除回差阈值";
CM_ SG_ 2416635510 S2P_Lmt2_Under_Ucell1_54 "电池单体放电电压一级报警值";
CM_ SG_ 2416635510 S2P_Lmt2_Under_DUcell1_54 "单体欠压1级告警消除回差阈值";
CM_ SG_ 2416635510 S2P_Lmt2_Under_Ucell2_54 "电池单体放电电压二级报警值";
CM_ SG_ 2416635510 S2P_Lmt2_Under_DUcell2_54 "单体欠压2级告警消除回差阈值";
CM_ SG_ 2416635511 S2P_Lmt2_Under_Ucell1_55 "电池单体放电电压一级报警值";
CM_ SG_ 2416635511 S2P_Lmt2_Under_DUcell1_55 "单体欠压1级告警消除回差阈值";
CM_ SG_ 2416635511 S2P_Lmt2_Under_Ucell2_55 "电池单体放电电压二级报警值";
CM_ SG_ 2416635511 S2P_Lmt2_Under_DUcell2_55 "单体欠压2级告警消除回差阈值";
CM_ SG_ 2416635512 S2P_Lmt2_Under_Ucell1_56 "电池单体放电电压一级报警值";
CM_ SG_ 2416635512 S2P_Lmt2_Under_DUcell1_56 "单体欠压1级告警消除回差阈值";
CM_ SG_ 2416635512 S2P_Lmt2_Under_Ucell2_56 "电池单体放电电压二级报警值";
CM_ SG_ 2416635512 S2P_Lmt2_Under_DUcell2_56 "单体欠压2级告警消除回差阈值";
CM_ SG_ 2416635513 S2P_Lmt2_Under_Ucell1_57 "电池单体放电电压一级报警值";
CM_ SG_ 2416635513 S2P_Lmt2_Under_DUcell1_57 "单体欠压1级告警消除回差阈值";
CM_ SG_ 2416635513 S2P_Lmt2_Under_Ucell2_57 "电池单体放电电压二级报警值";
CM_ SG_ 2416635513 S2P_Lmt2_Under_DUcell2_57 "单体欠压2级告警消除回差阈值";
CM_ SG_ 2416635514 S2P_Lmt2_Under_Ucell1_58 "电池单体放电电压一级报警值";
CM_ SG_ 2416635514 S2P_Lmt2_Under_DUcell1_58 "单体欠压1级告警消除回差阈值";
CM_ SG_ 2416635514 S2P_Lmt2_Under_Ucell2_58 "电池单体放电电压二级报警值";
CM_ SG_ 2416635514 S2P_Lmt2_Under_DUcell2_58 "单体欠压2级告警消除回差阈值";
CM_ SG_ 2416635515 S2P_Lmt2_Under_Ucell1_59 "电池单体放电电压一级报警值";
CM_ SG_ 2416635515 S2P_Lmt2_Under_DUcell1_59 "单体欠压1级告警消除回差阈值";
CM_ SG_ 2416635515 S2P_Lmt2_Under_Ucell2_59 "电池单体放电电压二级报警值";
CM_ SG_ 2416635515 S2P_Lmt2_Under_DUcell2_59 "单体欠压2级告警消除回差阈值";
CM_ SG_ 2416635516 S2P_Lmt2_Under_Ucell1_60 "电池单体放电电压一级报警值";
CM_ SG_ 2416635516 S2P_Lmt2_Under_DUcell1_60 "单体欠压1级告警消除回差阈值";
CM_ SG_ 2416635516 S2P_Lmt2_Under_Ucell2_60 "电池单体放电电压二级报警值";
CM_ SG_ 2416635516 S2P_Lmt2_Under_DUcell2_60 "单体欠压2级告警消除回差阈值";
CM_ SG_ 2416635517 S2P_Lmt2_Under_Ucell1_61 "电池单体放电电压一级报警值";
CM_ SG_ 2416635517 S2P_Lmt2_Under_DUcell1_61 "单体欠压1级告警消除回差阈值";
CM_ SG_ 2416635517 S2P_Lmt2_Under_Ucell2_61 "电池单体放电电压二级报警值";
CM_ SG_ 2416635517 S2P_Lmt2_Under_DUcell2_61 "单体欠压2级告警消除回差阈值";
CM_ SG_ 2416635518 S2P_Lmt2_Under_Ucell1_62 "电池单体放电电压一级报警值";
CM_ SG_ 2416635518 S2P_Lmt2_Under_DUcell1_62 "单体欠压1级告警消除回差阈值";
CM_ SG_ 2416635518 S2P_Lmt2_Under_Ucell2_62 "电池单体放电电压二级报警值";
CM_ SG_ 2416635518 S2P_Lmt2_Under_DUcell2_62 "单体欠压2级告警消除回差阈值";
CM_ SG_ 2416635519 S2P_Lmt2_Under_Ucell1_63 "电池单体放电电压一级报警值";
CM_ SG_ 2416635519 S2P_Lmt2_Under_DUcell1_63 "单体欠压1级告警消除回差阈值";
CM_ SG_ 2416635519 S2P_Lmt2_Under_Ucell2_63 "电池单体放电电压二级报警值";
CM_ SG_ 2416635519 S2P_Lmt2_Under_DUcell2_63 "单体欠压2级告警消除回差阈值";
CM_ SG_ 2416700993 S2P_Lmt3_Over_Ucell3_01 "电池单体充电电压三级报警值";
CM_ SG_ 2416700993 S2P_Lmt3_Over_DUcell3_01 "单体过压3级告警消除回差阈值";
CM_ SG_ 2416700993 S2P_Lmt3_Under_Ucell3_01 "电池单体放电电压三级报警值";
CM_ SG_ 2416700993 S2P_Lmt3_Under_DUcell3_01 "单体欠压3级告警消除回差阈值";
CM_ SG_ 2416700994 S2P_Lmt3_Over_Ucell3_02 "电池单体充电电压三级报警值";
CM_ SG_ 2416700994 S2P_Lmt3_Over_DUcell3_02 "单体过压3级告警消除回差阈值";
CM_ SG_ 2416700994 S2P_Lmt3_Under_Ucell3_02 "电池单体放电电压三级报警值";
CM_ SG_ 2416700994 S2P_Lmt3_Under_DUcell3_02 "单体欠压3级告警消除回差阈值";
CM_ SG_ 2416700995 S2P_Lmt3_Over_Ucell3_03 "电池单体充电电压三级报警值";
CM_ SG_ 2416700995 S2P_Lmt3_Over_DUcell3_03 "单体过压3级告警消除回差阈值";
CM_ SG_ 2416700995 S2P_Lmt3_Under_Ucell3_03 "电池单体放电电压三级报警值";
CM_ SG_ 2416700995 S2P_Lmt3_Under_DUcell3_03 "单体欠压3级告警消除回差阈值";
CM_ SG_ 2416700996 S2P_Lmt3_Over_Ucell3_04 "电池单体充电电压三级报警值";
CM_ SG_ 2416700996 S2P_Lmt3_Over_DUcell3_04 "单体过压3级告警消除回差阈值";
CM_ SG_ 2416700996 S2P_Lmt3_Under_Ucell3_04 "电池单体放电电压三级报警值";
CM_ SG_ 2416700996 S2P_Lmt3_Under_DUcell3_04 "单体欠压3级告警消除回差阈值";
CM_ SG_ 2416700997 S2P_Lmt3_Over_Ucell3_05 "电池单体充电电压三级报警值";
CM_ SG_ 2416700997 S2P_Lmt3_Over_DUcell3_05 "单体过压3级告警消除回差阈值";
CM_ SG_ 2416700997 S2P_Lmt3_Under_Ucell3_05 "电池单体放电电压三级报警值";
CM_ SG_ 2416700997 S2P_Lmt3_Under_DUcell3_05 "单体欠压3级告警消除回差阈值";
CM_ SG_ 2416700998 S2P_Lmt3_Over_Ucell3_06 "电池单体充电电压三级报警值";
CM_ SG_ 2416700998 S2P_Lmt3_Over_DUcell3_06 "单体过压3级告警消除回差阈值";
CM_ SG_ 2416700998 S2P_Lmt3_Under_Ucell3_06 "电池单体放电电压三级报警值";
CM_ SG_ 2416700998 S2P_Lmt3_Under_DUcell3_06 "单体欠压3级告警消除回差阈值";
CM_ SG_ 2416700999 S2P_Lmt3_Over_Ucell3_07 "电池单体充电电压三级报警值";
CM_ SG_ 2416700999 S2P_Lmt3_Over_DUcell3_07 "单体过压3级告警消除回差阈值";
CM_ SG_ 2416700999 S2P_Lmt3_Under_Ucell3_07 "电池单体放电电压三级报警值";
CM_ SG_ 2416700999 S2P_Lmt3_Under_DUcell3_07 "单体欠压3级告警消除回差阈值";
CM_ SG_ 2416701000 S2P_Lmt3_Over_Ucell3_08 "电池单体充电电压三级报警值";
CM_ SG_ 2416701000 S2P_Lmt3_Over_DUcell3_08 "单体过压3级告警消除回差阈值";
CM_ SG_ 2416701000 S2P_Lmt3_Under_Ucell3_08 "电池单体放电电压三级报警值";
CM_ SG_ 2416701000 S2P_Lmt3_Under_DUcell3_08 "单体欠压3级告警消除回差阈值";
CM_ SG_ 2416701001 S2P_Lmt3_Over_Ucell3_09 "电池单体充电电压三级报警值";
CM_ SG_ 2416701001 S2P_Lmt3_Over_DUcell3_09 "单体过压3级告警消除回差阈值";
CM_ SG_ 2416701001 S2P_Lmt3_Under_Ucell3_09 "电池单体放电电压三级报警值";
CM_ SG_ 2416701001 S2P_Lmt3_Under_DUcell3_09 "单体欠压3级告警消除回差阈值";
CM_ SG_ 2416701002 S2P_Lmt3_Over_Ucell3_10 "电池单体充电电压三级报警值";
CM_ SG_ 2416701002 S2P_Lmt3_Over_DUcell3_10 "单体过压3级告警消除回差阈值";
CM_ SG_ 2416701002 S2P_Lmt3_Under_Ucell3_10 "电池单体放电电压三级报警值";
CM_ SG_ 2416701002 S2P_Lmt3_Under_DUcell3_10 "单体欠压3级告警消除回差阈值";
CM_ SG_ 2416701003 S2P_Lmt3_Over_Ucell3_11 "电池单体充电电压三级报警值";
CM_ SG_ 2416701003 S2P_Lmt3_Over_DUcell3_11 "单体过压3级告警消除回差阈值";
CM_ SG_ 2416701003 S2P_Lmt3_Under_Ucell3_11 "电池单体放电电压三级报警值";
CM_ SG_ 2416701003 S2P_Lmt3_Under_DUcell3_11 "单体欠压3级告警消除回差阈值";
CM_ SG_ 2416701004 S2P_Lmt3_Over_Ucell3_12 "电池单体充电电压三级报警值";
CM_ SG_ 2416701004 S2P_Lmt3_Over_DUcell3_12 "单体过压3级告警消除回差阈值";
CM_ SG_ 2416701004 S2P_Lmt3_Under_Ucell3_12 "电池单体放电电压三级报警值";
CM_ SG_ 2416701004 S2P_Lmt3_Under_DUcell3_12 "单体欠压3级告警消除回差阈值";
CM_ SG_ 2416701005 S2P_Lmt3_Over_Ucell3_13 "电池单体充电电压三级报警值";
CM_ SG_ 2416701005 S2P_Lmt3_Over_DUcell3_13 "单体过压3级告警消除回差阈值";
CM_ SG_ 2416701005 S2P_Lmt3_Under_Ucell3_13 "电池单体放电电压三级报警值";
CM_ SG_ 2416701005 S2P_Lmt3_Under_DUcell3_13 "单体欠压3级告警消除回差阈值";
CM_ SG_ 2416701006 S2P_Lmt3_Over_Ucell3_14 "电池单体充电电压三级报警值";
CM_ SG_ 2416701006 S2P_Lmt3_Over_DUcell3_14 "单体过压3级告警消除回差阈值";
CM_ SG_ 2416701006 S2P_Lmt3_Under_Ucell3_14 "电池单体放电电压三级报警值";
CM_ SG_ 2416701006 S2P_Lmt3_Under_DUcell3_14 "单体欠压3级告警消除回差阈值";
CM_ SG_ 2416701007 S2P_Lmt3_Over_Ucell3_15 "电池单体充电电压三级报警值";
CM_ SG_ 2416701007 S2P_Lmt3_Over_DUcell3_15 "单体过压3级告警消除回差阈值";
CM_ SG_ 2416701007 S2P_Lmt3_Under_Ucell3_15 "电池单体放电电压三级报警值";
CM_ SG_ 2416701007 S2P_Lmt3_Under_DUcell3_15 "单体欠压3级告警消除回差阈值";
CM_ SG_ 2416701008 S2P_Lmt3_Over_Ucell3_16 "电池单体充电电压三级报警值";
CM_ SG_ 2416701008 S2P_Lmt3_Over_DUcell3_16 "单体过压3级告警消除回差阈值";
CM_ SG_ 2416701008 S2P_Lmt3_Under_Ucell3_16 "电池单体放电电压三级报警值";
CM_ SG_ 2416701008 S2P_Lmt3_Under_DUcell3_16 "单体欠压3级告警消除回差阈值";
CM_ SG_ 2416701009 S2P_Lmt3_Over_Ucell3_17 "电池单体充电电压三级报警值";
CM_ SG_ 2416701009 S2P_Lmt3_Over_DUcell3_17 "单体过压3级告警消除回差阈值";
CM_ SG_ 2416701009 S2P_Lmt3_Under_Ucell3_17 "电池单体放电电压三级报警值";
CM_ SG_ 2416701009 S2P_Lmt3_Under_DUcell3_17 "单体欠压3级告警消除回差阈值";
CM_ SG_ 2416701010 S2P_Lmt3_Over_Ucell3_18 "电池单体充电电压三级报警值";
CM_ SG_ 2416701010 S2P_Lmt3_Over_DUcell3_18 "单体过压3级告警消除回差阈值";
CM_ SG_ 2416701010 S2P_Lmt3_Under_Ucell3_18 "电池单体放电电压三级报警值";
CM_ SG_ 2416701010 S2P_Lmt3_Under_DUcell3_18 "单体欠压3级告警消除回差阈值";
CM_ SG_ 2416701011 S2P_Lmt3_Over_Ucell3_19 "电池单体充电电压三级报警值";
CM_ SG_ 2416701011 S2P_Lmt3_Over_DUcell3_19 "单体过压3级告警消除回差阈值";
CM_ SG_ 2416701011 S2P_Lmt3_Under_Ucell3_19 "电池单体放电电压三级报警值";
CM_ SG_ 2416701011 S2P_Lmt3_Under_DUcell3_19 "单体欠压3级告警消除回差阈值";
CM_ SG_ 2416701012 S2P_Lmt3_Over_Ucell3_20 "电池单体充电电压三级报警值";
CM_ SG_ 2416701012 S2P_Lmt3_Over_DUcell3_20 "单体过压3级告警消除回差阈值";
CM_ SG_ 2416701012 S2P_Lmt3_Under_Ucell3_20 "电池单体放电电压三级报警值";
CM_ SG_ 2416701012 S2P_Lmt3_Under_DUcell3_20 "单体欠压3级告警消除回差阈值";
CM_ SG_ 2416701013 S2P_Lmt3_Over_Ucell3_21 "电池单体充电电压三级报警值";
CM_ SG_ 2416701013 S2P_Lmt3_Over_DUcell3_21 "单体过压3级告警消除回差阈值";
CM_ SG_ 2416701013 S2P_Lmt3_Under_Ucell3_21 "电池单体放电电压三级报警值";
CM_ SG_ 2416701013 S2P_Lmt3_Under_DUcell3_21 "单体欠压3级告警消除回差阈值";
CM_ SG_ 2416701014 S2P_Lmt3_Over_Ucell3_22 "电池单体充电电压三级报警值";
CM_ SG_ 2416701014 S2P_Lmt3_Over_DUcell3_22 "单体过压3级告警消除回差阈值";
CM_ SG_ 2416701014 S2P_Lmt3_Under_Ucell3_22 "电池单体放电电压三级报警值";
CM_ SG_ 2416701014 S2P_Lmt3_Under_DUcell3_22 "单体欠压3级告警消除回差阈值";
CM_ SG_ 2416701015 S2P_Lmt3_Over_Ucell3_23 "电池单体充电电压三级报警值";
CM_ SG_ 2416701015 S2P_Lmt3_Over_DUcell3_23 "单体过压3级告警消除回差阈值";
CM_ SG_ 2416701015 S2P_Lmt3_Under_Ucell3_23 "电池单体放电电压三级报警值";
CM_ SG_ 2416701015 S2P_Lmt3_Under_DUcell3_23 "单体欠压3级告警消除回差阈值";
CM_ SG_ 2416701016 S2P_Lmt3_Over_Ucell3_24 "电池单体充电电压三级报警值";
CM_ SG_ 2416701016 S2P_Lmt3_Over_DUcell3_24 "单体过压3级告警消除回差阈值";
CM_ SG_ 2416701016 S2P_Lmt3_Under_Ucell3_24 "电池单体放电电压三级报警值";
CM_ SG_ 2416701016 S2P_Lmt3_Under_DUcell3_24 "单体欠压3级告警消除回差阈值";
CM_ SG_ 2416701017 S2P_Lmt3_Over_Ucell3_25 "电池单体充电电压三级报警值";
CM_ SG_ 2416701017 S2P_Lmt3_Over_DUcell3_25 "单体过压3级告警消除回差阈值";
CM_ SG_ 2416701017 S2P_Lmt3_Under_Ucell3_25 "电池单体放电电压三级报警值";
CM_ SG_ 2416701017 S2P_Lmt3_Under_DUcell3_25 "单体欠压3级告警消除回差阈值";
CM_ SG_ 2416701018 S2P_Lmt3_Over_Ucell3_26 "电池单体充电电压三级报警值";
CM_ SG_ 2416701018 S2P_Lmt3_Over_DUcell3_26 "单体过压3级告警消除回差阈值";
CM_ SG_ 2416701018 S2P_Lmt3_Under_Ucell3_26 "电池单体放电电压三级报警值";
CM_ SG_ 2416701018 S2P_Lmt3_Under_DUcell3_26 "单体欠压3级告警消除回差阈值";
CM_ SG_ 2416701019 S2P_Lmt3_Over_Ucell3_27 "电池单体充电电压三级报警值";
CM_ SG_ 2416701019 S2P_Lmt3_Over_DUcell3_27 "单体过压3级告警消除回差阈值";
CM_ SG_ 2416701019 S2P_Lmt3_Under_Ucell3_27 "电池单体放电电压三级报警值";
CM_ SG_ 2416701019 S2P_Lmt3_Under_DUcell3_27 "单体欠压3级告警消除回差阈值";
CM_ SG_ 2416701020 S2P_Lmt3_Over_Ucell3_28 "电池单体充电电压三级报警值";
CM_ SG_ 2416701020 S2P_Lmt3_Over_DUcell3_28 "单体过压3级告警消除回差阈值";
CM_ SG_ 2416701020 S2P_Lmt3_Under_Ucell3_28 "电池单体放电电压三级报警值";
CM_ SG_ 2416701020 S2P_Lmt3_Under_DUcell3_28 "单体欠压3级告警消除回差阈值";
CM_ SG_ 2416701021 S2P_Lmt3_Over_Ucell3_29 "电池单体充电电压三级报警值";
CM_ SG_ 2416701021 S2P_Lmt3_Over_DUcell3_29 "单体过压3级告警消除回差阈值";
CM_ SG_ 2416701021 S2P_Lmt3_Under_Ucell3_29 "电池单体放电电压三级报警值";
CM_ SG_ 2416701021 S2P_Lmt3_Under_DUcell3_29 "单体欠压3级告警消除回差阈值";
CM_ SG_ 2416701022 S2P_Lmt3_Over_Ucell3_30 "电池单体充电电压三级报警值";
CM_ SG_ 2416701022 S2P_Lmt3_Over_DUcell3_30 "单体过压3级告警消除回差阈值";
CM_ SG_ 2416701022 S2P_Lmt3_Under_Ucell3_30 "电池单体放电电压三级报警值";
CM_ SG_ 2416701022 S2P_Lmt3_Under_DUcell3_30 "单体欠压3级告警消除回差阈值";
CM_ SG_ 2416701023 S2P_Lmt3_Over_Ucell3_31 "电池单体充电电压三级报警值";
CM_ SG_ 2416701023 S2P_Lmt3_Over_DUcell3_31 "单体过压3级告警消除回差阈值";
CM_ SG_ 2416701023 S2P_Lmt3_Under_Ucell3_31 "电池单体放电电压三级报警值";
CM_ SG_ 2416701023 S2P_Lmt3_Under_DUcell3_31 "单体欠压3级告警消除回差阈值";
CM_ SG_ 2416701024 S2P_Lmt3_Over_Ucell3_32 "电池单体充电电压三级报警值";
CM_ SG_ 2416701024 S2P_Lmt3_Over_DUcell3_32 "单体过压3级告警消除回差阈值";
CM_ SG_ 2416701024 S2P_Lmt3_Under_Ucell3_32 "电池单体放电电压三级报警值";
CM_ SG_ 2416701024 S2P_Lmt3_Under_DUcell3_32 "单体欠压3级告警消除回差阈值";
CM_ SG_ 2416701025 S2P_Lmt3_Over_Ucell3_33 "电池单体充电电压三级报警值";
CM_ SG_ 2416701025 S2P_Lmt3_Over_DUcell3_33 "单体过压3级告警消除回差阈值";
CM_ SG_ 2416701025 S2P_Lmt3_Under_Ucell3_33 "电池单体放电电压三级报警值";
CM_ SG_ 2416701025 S2P_Lmt3_Under_DUcell3_33 "单体欠压3级告警消除回差阈值";
CM_ SG_ 2416701026 S2P_Lmt3_Over_Ucell3_34 "电池单体充电电压三级报警值";
CM_ SG_ 2416701026 S2P_Lmt3_Over_DUcell3_34 "单体过压3级告警消除回差阈值";
CM_ SG_ 2416701026 S2P_Lmt3_Under_Ucell3_34 "电池单体放电电压三级报警值";
CM_ SG_ 2416701026 S2P_Lmt3_Under_DUcell3_34 "单体欠压3级告警消除回差阈值";
CM_ SG_ 2416701027 S2P_Lmt3_Over_Ucell3_35 "电池单体充电电压三级报警值";
CM_ SG_ 2416701027 S2P_Lmt3_Over_DUcell3_35 "单体过压3级告警消除回差阈值";
CM_ SG_ 2416701027 S2P_Lmt3_Under_Ucell3_35 "电池单体放电电压三级报警值";
CM_ SG_ 2416701027 S2P_Lmt3_Under_DUcell3_35 "单体欠压3级告警消除回差阈值";
CM_ SG_ 2416701028 S2P_Lmt3_Over_Ucell3_36 "电池单体充电电压三级报警值";
CM_ SG_ 2416701028 S2P_Lmt3_Over_DUcell3_36 "单体过压3级告警消除回差阈值";
CM_ SG_ 2416701028 S2P_Lmt3_Under_Ucell3_36 "电池单体放电电压三级报警值";
CM_ SG_ 2416701028 S2P_Lmt3_Under_DUcell3_36 "单体欠压3级告警消除回差阈值";
CM_ SG_ 2416701029 S2P_Lmt3_Over_Ucell3_37 "电池单体充电电压三级报警值";
CM_ SG_ 2416701029 S2P_Lmt3_Over_DUcell3_37 "单体过压3级告警消除回差阈值";
CM_ SG_ 2416701029 S2P_Lmt3_Under_Ucell3_37 "电池单体放电电压三级报警值";
CM_ SG_ 2416701029 S2P_Lmt3_Under_DUcell3_37 "单体欠压3级告警消除回差阈值";
CM_ SG_ 2416701030 S2P_Lmt3_Over_Ucell3_38 "电池单体充电电压三级报警值";
CM_ SG_ 2416701030 S2P_Lmt3_Over_DUcell3_38 "单体过压3级告警消除回差阈值";
CM_ SG_ 2416701030 S2P_Lmt3_Under_Ucell3_38 "电池单体放电电压三级报警值";
CM_ SG_ 2416701030 S2P_Lmt3_Under_DUcell3_38 "单体欠压3级告警消除回差阈值";
CM_ SG_ 2416701031 S2P_Lmt3_Over_Ucell3_39 "电池单体充电电压三级报警值";
CM_ SG_ 2416701031 S2P_Lmt3_Over_DUcell3_39 "单体过压3级告警消除回差阈值";
CM_ SG_ 2416701031 S2P_Lmt3_Under_Ucell3_39 "电池单体放电电压三级报警值";
CM_ SG_ 2416701031 S2P_Lmt3_Under_DUcell3_39 "单体欠压3级告警消除回差阈值";
CM_ SG_ 2416701032 S2P_Lmt3_Over_Ucell3_40 "电池单体充电电压三级报警值";
CM_ SG_ 2416701032 S2P_Lmt3_Over_DUcell3_40 "单体过压3级告警消除回差阈值";
CM_ SG_ 2416701032 S2P_Lmt3_Under_Ucell3_40 "电池单体放电电压三级报警值";
CM_ SG_ 2416701032 S2P_Lmt3_Under_DUcell3_40 "单体欠压3级告警消除回差阈值";
CM_ SG_ 2416701033 S2P_Lmt3_Over_Ucell3_41 "电池单体充电电压三级报警值";
CM_ SG_ 2416701033 S2P_Lmt3_Over_DUcell3_41 "单体过压3级告警消除回差阈值";
CM_ SG_ 2416701033 S2P_Lmt3_Under_Ucell3_41 "电池单体放电电压三级报警值";
CM_ SG_ 2416701033 S2P_Lmt3_Under_DUcell3_41 "单体欠压3级告警消除回差阈值";
CM_ SG_ 2416701034 S2P_Lmt3_Over_Ucell3_42 "电池单体充电电压三级报警值";
CM_ SG_ 2416701034 S2P_Lmt3_Over_DUcell3_42 "单体过压3级告警消除回差阈值";
CM_ SG_ 2416701034 S2P_Lmt3_Under_Ucell3_42 "电池单体放电电压三级报警值";
CM_ SG_ 2416701034 S2P_Lmt3_Under_DUcell3_42 "单体欠压3级告警消除回差阈值";
CM_ SG_ 2416701035 S2P_Lmt3_Over_Ucell3_43 "电池单体充电电压三级报警值";
CM_ SG_ 2416701035 S2P_Lmt3_Over_DUcell3_43 "单体过压3级告警消除回差阈值";
CM_ SG_ 2416701035 S2P_Lmt3_Under_Ucell3_43 "电池单体放电电压三级报警值";
CM_ SG_ 2416701035 S2P_Lmt3_Under_DUcell3_43 "单体欠压3级告警消除回差阈值";
CM_ SG_ 2416701036 S2P_Lmt3_Over_Ucell3_44 "电池单体充电电压三级报警值";
CM_ SG_ 2416701036 S2P_Lmt3_Over_DUcell3_44 "单体过压3级告警消除回差阈值";
CM_ SG_ 2416701036 S2P_Lmt3_Under_Ucell3_44 "电池单体放电电压三级报警值";
CM_ SG_ 2416701036 S2P_Lmt3_Under_DUcell3_44 "单体欠压3级告警消除回差阈值";
CM_ SG_ 2416701037 S2P_Lmt3_Over_Ucell3_45 "电池单体充电电压三级报警值";
CM_ SG_ 2416701037 S2P_Lmt3_Over_DUcell3_45 "单体过压3级告警消除回差阈值";
CM_ SG_ 2416701037 S2P_Lmt3_Under_Ucell3_45 "电池单体放电电压三级报警值";
CM_ SG_ 2416701037 S2P_Lmt3_Under_DUcell3_45 "单体欠压3级告警消除回差阈值";
CM_ SG_ 2416701038 S2P_Lmt3_Over_Ucell3_46 "电池单体充电电压三级报警值";
CM_ SG_ 2416701038 S2P_Lmt3_Over_DUcell3_46 "单体过压3级告警消除回差阈值";
CM_ SG_ 2416701038 S2P_Lmt3_Under_Ucell3_46 "电池单体放电电压三级报警值";
CM_ SG_ 2416701038 S2P_Lmt3_Under_DUcell3_46 "单体欠压3级告警消除回差阈值";
CM_ SG_ 2416701039 S2P_Lmt3_Over_Ucell3_47 "电池单体充电电压三级报警值";
CM_ SG_ 2416701039 S2P_Lmt3_Over_DUcell3_47 "单体过压3级告警消除回差阈值";
CM_ SG_ 2416701039 S2P_Lmt3_Under_Ucell3_47 "电池单体放电电压三级报警值";
CM_ SG_ 2416701039 S2P_Lmt3_Under_DUcell3_47 "单体欠压3级告警消除回差阈值";
CM_ SG_ 2416701040 S2P_Lmt3_Over_Ucell3_48 "电池单体充电电压三级报警值";
CM_ SG_ 2416701040 S2P_Lmt3_Over_DUcell3_48 "单体过压3级告警消除回差阈值";
CM_ SG_ 2416701040 S2P_Lmt3_Under_Ucell3_48 "电池单体放电电压三级报警值";
CM_ SG_ 2416701040 S2P_Lmt3_Under_DUcell3_48 "单体欠压3级告警消除回差阈值";
CM_ SG_ 2416701041 S2P_Lmt3_Over_Ucell3_49 "电池单体充电电压三级报警值";
CM_ SG_ 2416701041 S2P_Lmt3_Over_DUcell3_49 "单体过压3级告警消除回差阈值";
CM_ SG_ 2416701041 S2P_Lmt3_Under_Ucell3_49 "电池单体放电电压三级报警值";
CM_ SG_ 2416701041 S2P_Lmt3_Under_DUcell3_49 "单体欠压3级告警消除回差阈值";
CM_ SG_ 2416701042 S2P_Lmt3_Over_Ucell3_50 "电池单体充电电压三级报警值";
CM_ SG_ 2416701042 S2P_Lmt3_Over_DUcell3_50 "单体过压3级告警消除回差阈值";
CM_ SG_ 2416701042 S2P_Lmt3_Under_Ucell3_50 "电池单体放电电压三级报警值";
CM_ SG_ 2416701042 S2P_Lmt3_Under_DUcell3_50 "单体欠压3级告警消除回差阈值";
CM_ SG_ 2416701043 S2P_Lmt3_Over_Ucell3_51 "电池单体充电电压三级报警值";
CM_ SG_ 2416701043 S2P_Lmt3_Over_DUcell3_51 "单体过压3级告警消除回差阈值";
CM_ SG_ 2416701043 S2P_Lmt3_Under_Ucell3_51 "电池单体放电电压三级报警值";
CM_ SG_ 2416701043 S2P_Lmt3_Under_DUcell3_51 "单体欠压3级告警消除回差阈值";
CM_ SG_ 2416701044 S2P_Lmt3_Over_Ucell3_52 "电池单体充电电压三级报警值";
CM_ SG_ 2416701044 S2P_Lmt3_Over_DUcell3_52 "单体过压3级告警消除回差阈值";
CM_ SG_ 2416701044 S2P_Lmt3_Under_Ucell3_52 "电池单体放电电压三级报警值";
CM_ SG_ 2416701044 S2P_Lmt3_Under_DUcell3_52 "单体欠压3级告警消除回差阈值";
CM_ SG_ 2416701045 S2P_Lmt3_Over_Ucell3_53 "电池单体充电电压三级报警值";
CM_ SG_ 2416701045 S2P_Lmt3_Over_DUcell3_53 "单体过压3级告警消除回差阈值";
CM_ SG_ 2416701045 S2P_Lmt3_Under_Ucell3_53 "电池单体放电电压三级报警值";
CM_ SG_ 2416701045 S2P_Lmt3_Under_DUcell3_53 "单体欠压3级告警消除回差阈值";
CM_ SG_ 2416701046 S2P_Lmt3_Over_Ucell3_54 "电池单体充电电压三级报警值";
CM_ SG_ 2416701046 S2P_Lmt3_Over_DUcell3_54 "单体过压3级告警消除回差阈值";
CM_ SG_ 2416701046 S2P_Lmt3_Under_Ucell3_54 "电池单体放电电压三级报警值";
CM_ SG_ 2416701046 S2P_Lmt3_Under_DUcell3_54 "单体欠压3级告警消除回差阈值";
CM_ SG_ 2416701047 S2P_Lmt3_Over_Ucell3_55 "电池单体充电电压三级报警值";
CM_ SG_ 2416701047 S2P_Lmt3_Over_DUcell3_55 "单体过压3级告警消除回差阈值";
CM_ SG_ 2416701047 S2P_Lmt3_Under_Ucell3_55 "电池单体放电电压三级报警值";
CM_ SG_ 2416701047 S2P_Lmt3_Under_DUcell3_55 "单体欠压3级告警消除回差阈值";
CM_ SG_ 2416701048 S2P_Lmt3_Over_Ucell3_56 "电池单体充电电压三级报警值";
CM_ SG_ 2416701048 S2P_Lmt3_Over_DUcell3_56 "单体过压3级告警消除回差阈值";
CM_ SG_ 2416701048 S2P_Lmt3_Under_Ucell3_56 "电池单体放电电压三级报警值";
CM_ SG_ 2416701048 S2P_Lmt3_Under_DUcell3_56 "单体欠压3级告警消除回差阈值";
CM_ SG_ 2416701049 S2P_Lmt3_Over_Ucell3_57 "电池单体充电电压三级报警值";
CM_ SG_ 2416701049 S2P_Lmt3_Over_DUcell3_57 "单体过压3级告警消除回差阈值";
CM_ SG_ 2416701049 S2P_Lmt3_Under_Ucell3_57 "电池单体放电电压三级报警值";
CM_ SG_ 2416701049 S2P_Lmt3_Under_DUcell3_57 "单体欠压3级告警消除回差阈值";
CM_ SG_ 2416701050 S2P_Lmt3_Over_Ucell3_58 "电池单体充电电压三级报警值";
CM_ SG_ 2416701050 S2P_Lmt3_Over_DUcell3_58 "单体过压3级告警消除回差阈值";
CM_ SG_ 2416701050 S2P_Lmt3_Under_Ucell3_58 "电池单体放电电压三级报警值";
CM_ SG_ 2416701050 S2P_Lmt3_Under_DUcell3_58 "单体欠压3级告警消除回差阈值";
CM_ SG_ 2416701051 S2P_Lmt3_Over_Ucell3_59 "电池单体充电电压三级报警值";
CM_ SG_ 2416701051 S2P_Lmt3_Over_DUcell3_59 "单体过压3级告警消除回差阈值";
CM_ SG_ 2416701051 S2P_Lmt3_Under_Ucell3_59 "电池单体放电电压三级报警值";
CM_ SG_ 2416701051 S2P_Lmt3_Under_DUcell3_59 "单体欠压3级告警消除回差阈值";
CM_ SG_ 2416701052 S2P_Lmt3_Over_Ucell3_60 "电池单体充电电压三级报警值";
CM_ SG_ 2416701052 S2P_Lmt3_Over_DUcell3_60 "单体过压3级告警消除回差阈值";
CM_ SG_ 2416701052 S2P_Lmt3_Under_Ucell3_60 "电池单体放电电压三级报警值";
CM_ SG_ 2416701052 S2P_Lmt3_Under_DUcell3_60 "单体欠压3级告警消除回差阈值";
CM_ SG_ 2416701053 S2P_Lmt3_Over_Ucell3_61 "电池单体充电电压三级报警值";
CM_ SG_ 2416701053 S2P_Lmt3_Over_DUcell3_61 "单体过压3级告警消除回差阈值";
CM_ SG_ 2416701053 S2P_Lmt3_Under_Ucell3_61 "电池单体放电电压三级报警值";
CM_ SG_ 2416701053 S2P_Lmt3_Under_DUcell3_61 "单体欠压3级告警消除回差阈值";
CM_ SG_ 2416701054 S2P_Lmt3_Over_Ucell3_62 "电池单体充电电压三级报警值";
CM_ SG_ 2416701054 S2P_Lmt3_Over_DUcell3_62 "单体过压3级告警消除回差阈值";
CM_ SG_ 2416701054 S2P_Lmt3_Under_Ucell3_62 "电池单体放电电压三级报警值";
CM_ SG_ 2416701054 S2P_Lmt3_Under_DUcell3_62 "单体欠压3级告警消除回差阈值";
CM_ SG_ 2416701055 S2P_Lmt3_Over_Ucell3_63 "电池单体充电电压三级报警值";
CM_ SG_ 2416701055 S2P_Lmt3_Over_DUcell3_63 "单体过压3级告警消除回差阈值";
CM_ SG_ 2416701055 S2P_Lmt3_Under_Ucell3_63 "电池单体放电电压三级报警值";
CM_ SG_ 2416701055 S2P_Lmt3_Under_DUcell3_63 "单体欠压3级告警消除回差阈值";
CM_ SG_ 2416766529 S2P_Lmt4_Over_DeltUcell1_01 "单体压差过大1级告警阈值";
CM_ SG_ 2416766529 S2P_Lmt4_Over_DeltUcell2_01 "单体压差过大2级告警阈值";
CM_ SG_ 2416766529 S2P_Lmt4_Over_DeltUcell3_01 "单体压差过大3级告警阈值";
CM_ SG_ 2416766529 S2P_Lmt4_Over_DDeltUcell_01 "单体压差过大告警消除回差阈值";
CM_ SG_ 2416766530 S2P_Lmt4_Over_DeltUcell1_02 "单体压差过大1级告警阈值";
CM_ SG_ 2416766530 S2P_Lmt4_Over_DeltUcell2_02 "单体压差过大2级告警阈值";
CM_ SG_ 2416766530 S2P_Lmt4_Over_DeltUcell3_02 "单体压差过大3级告警阈值";
CM_ SG_ 2416766530 S2P_Lmt4_Over_DDeltUcell_02 "单体压差过大告警消除回差阈值";
CM_ SG_ 2416766531 S2P_Lmt4_Over_DeltUcell1_03 "单体压差过大1级告警阈值";
CM_ SG_ 2416766531 S2P_Lmt4_Over_DeltUcell2_03 "单体压差过大2级告警阈值";
CM_ SG_ 2416766531 S2P_Lmt4_Over_DeltUcell3_03 "单体压差过大3级告警阈值";
CM_ SG_ 2416766531 S2P_Lmt4_Over_DDeltUcell_03 "单体压差过大告警消除回差阈值";
CM_ SG_ 2416766532 S2P_Lmt4_Over_DeltUcell1_04 "单体压差过大1级告警阈值";
CM_ SG_ 2416766532 S2P_Lmt4_Over_DeltUcell2_04 "单体压差过大2级告警阈值";
CM_ SG_ 2416766532 S2P_Lmt4_Over_DeltUcell3_04 "单体压差过大3级告警阈值";
CM_ SG_ 2416766532 S2P_Lmt4_Over_DDeltUcell_04 "单体压差过大告警消除回差阈值";
CM_ SG_ 2416766533 S2P_Lmt4_Over_DeltUcell1_05 "单体压差过大1级告警阈值";
CM_ SG_ 2416766533 S2P_Lmt4_Over_DeltUcell2_05 "单体压差过大2级告警阈值";
CM_ SG_ 2416766533 S2P_Lmt4_Over_DeltUcell3_05 "单体压差过大3级告警阈值";
CM_ SG_ 2416766533 S2P_Lmt4_Over_DDeltUcell_05 "单体压差过大告警消除回差阈值";
CM_ SG_ 2416766534 S2P_Lmt4_Over_DeltUcell1_06 "单体压差过大1级告警阈值";
CM_ SG_ 2416766534 S2P_Lmt4_Over_DeltUcell2_06 "单体压差过大2级告警阈值";
CM_ SG_ 2416766534 S2P_Lmt4_Over_DeltUcell3_06 "单体压差过大3级告警阈值";
CM_ SG_ 2416766534 S2P_Lmt4_Over_DDeltUcell_06 "单体压差过大告警消除回差阈值";
CM_ SG_ 2416766535 S2P_Lmt4_Over_DeltUcell1_07 "单体压差过大1级告警阈值";
CM_ SG_ 2416766535 S2P_Lmt4_Over_DeltUcell2_07 "单体压差过大2级告警阈值";
CM_ SG_ 2416766535 S2P_Lmt4_Over_DeltUcell3_07 "单体压差过大3级告警阈值";
CM_ SG_ 2416766535 S2P_Lmt4_Over_DDeltUcell_07 "单体压差过大告警消除回差阈值";
CM_ SG_ 2416766536 S2P_Lmt4_Over_DeltUcell1_08 "单体压差过大1级告警阈值";
CM_ SG_ 2416766536 S2P_Lmt4_Over_DeltUcell2_08 "单体压差过大2级告警阈值";
CM_ SG_ 2416766536 S2P_Lmt4_Over_DeltUcell3_08 "单体压差过大3级告警阈值";
CM_ SG_ 2416766536 S2P_Lmt4_Over_DDeltUcell_08 "单体压差过大告警消除回差阈值";
CM_ SG_ 2416766537 S2P_Lmt4_Over_DeltUcell1_09 "单体压差过大1级告警阈值";
CM_ SG_ 2416766537 S2P_Lmt4_Over_DeltUcell2_09 "单体压差过大2级告警阈值";
CM_ SG_ 2416766537 S2P_Lmt4_Over_DeltUcell3_09 "单体压差过大3级告警阈值";
CM_ SG_ 2416766537 S2P_Lmt4_Over_DDeltUcell_09 "单体压差过大告警消除回差阈值";
CM_ SG_ 2416766538 S2P_Lmt4_Over_DeltUcell1_10 "单体压差过大1级告警阈值";
CM_ SG_ 2416766538 S2P_Lmt4_Over_DeltUcell2_10 "单体压差过大2级告警阈值";
CM_ SG_ 2416766538 S2P_Lmt4_Over_DeltUcell3_10 "单体压差过大3级告警阈值";
CM_ SG_ 2416766538 S2P_Lmt4_Over_DDeltUcell_10 "单体压差过大告警消除回差阈值";
CM_ SG_ 2416766539 S2P_Lmt4_Over_DeltUcell1_11 "单体压差过大1级告警阈值";
CM_ SG_ 2416766539 S2P_Lmt4_Over_DeltUcell2_11 "单体压差过大2级告警阈值";
CM_ SG_ 2416766539 S2P_Lmt4_Over_DeltUcell3_11 "单体压差过大3级告警阈值";
CM_ SG_ 2416766539 S2P_Lmt4_Over_DDeltUcell_11 "单体压差过大告警消除回差阈值";
CM_ SG_ 2416766540 S2P_Lmt4_Over_DeltUcell1_12 "单体压差过大1级告警阈值";
CM_ SG_ 2416766540 S2P_Lmt4_Over_DeltUcell2_12 "单体压差过大2级告警阈值";
CM_ SG_ 2416766540 S2P_Lmt4_Over_DeltUcell3_12 "单体压差过大3级告警阈值";
CM_ SG_ 2416766540 S2P_Lmt4_Over_DDeltUcell_12 "单体压差过大告警消除回差阈值";
CM_ SG_ 2416766541 S2P_Lmt4_Over_DeltUcell1_13 "单体压差过大1级告警阈值";
CM_ SG_ 2416766541 S2P_Lmt4_Over_DeltUcell2_13 "单体压差过大2级告警阈值";
CM_ SG_ 2416766541 S2P_Lmt4_Over_DeltUcell3_13 "单体压差过大3级告警阈值";
CM_ SG_ 2416766541 S2P_Lmt4_Over_DDeltUcell_13 "单体压差过大告警消除回差阈值";
CM_ SG_ 2416766542 S2P_Lmt4_Over_DeltUcell1_14 "单体压差过大1级告警阈值";
CM_ SG_ 2416766542 S2P_Lmt4_Over_DeltUcell2_14 "单体压差过大2级告警阈值";
CM_ SG_ 2416766542 S2P_Lmt4_Over_DeltUcell3_14 "单体压差过大3级告警阈值";
CM_ SG_ 2416766542 S2P_Lmt4_Over_DDeltUcell_14 "单体压差过大告警消除回差阈值";
CM_ SG_ 2416766543 S2P_Lmt4_Over_DeltUcell1_15 "单体压差过大1级告警阈值";
CM_ SG_ 2416766543 S2P_Lmt4_Over_DeltUcell2_15 "单体压差过大2级告警阈值";
CM_ SG_ 2416766543 S2P_Lmt4_Over_DeltUcell3_15 "单体压差过大3级告警阈值";
CM_ SG_ 2416766543 S2P_Lmt4_Over_DDeltUcell_15 "单体压差过大告警消除回差阈值";
CM_ SG_ 2416766544 S2P_Lmt4_Over_DeltUcell1_16 "单体压差过大1级告警阈值";
CM_ SG_ 2416766544 S2P_Lmt4_Over_DeltUcell2_16 "单体压差过大2级告警阈值";
CM_ SG_ 2416766544 S2P_Lmt4_Over_DeltUcell3_16 "单体压差过大3级告警阈值";
CM_ SG_ 2416766544 S2P_Lmt4_Over_DDeltUcell_16 "单体压差过大告警消除回差阈值";
CM_ SG_ 2416766545 S2P_Lmt4_Over_DeltUcell1_17 "单体压差过大1级告警阈值";
CM_ SG_ 2416766545 S2P_Lmt4_Over_DeltUcell2_17 "单体压差过大2级告警阈值";
CM_ SG_ 2416766545 S2P_Lmt4_Over_DeltUcell3_17 "单体压差过大3级告警阈值";
CM_ SG_ 2416766545 S2P_Lmt4_Over_DDeltUcell_17 "单体压差过大告警消除回差阈值";
CM_ SG_ 2416766546 S2P_Lmt4_Over_DeltUcell1_18 "单体压差过大1级告警阈值";
CM_ SG_ 2416766546 S2P_Lmt4_Over_DeltUcell2_18 "单体压差过大2级告警阈值";
CM_ SG_ 2416766546 S2P_Lmt4_Over_DeltUcell3_18 "单体压差过大3级告警阈值";
CM_ SG_ 2416766546 S2P_Lmt4_Over_DDeltUcell_18 "单体压差过大告警消除回差阈值";
CM_ SG_ 2416766547 S2P_Lmt4_Over_DeltUcell1_19 "单体压差过大1级告警阈值";
CM_ SG_ 2416766547 S2P_Lmt4_Over_DeltUcell2_19 "单体压差过大2级告警阈值";
CM_ SG_ 2416766547 S2P_Lmt4_Over_DeltUcell3_19 "单体压差过大3级告警阈值";
CM_ SG_ 2416766547 S2P_Lmt4_Over_DDeltUcell_19 "单体压差过大告警消除回差阈值";
CM_ SG_ 2416766548 S2P_Lmt4_Over_DeltUcell1_20 "单体压差过大1级告警阈值";
CM_ SG_ 2416766548 S2P_Lmt4_Over_DeltUcell2_20 "单体压差过大2级告警阈值";
CM_ SG_ 2416766548 S2P_Lmt4_Over_DeltUcell3_20 "单体压差过大3级告警阈值";
CM_ SG_ 2416766548 S2P_Lmt4_Over_DDeltUcell_20 "单体压差过大告警消除回差阈值";
CM_ SG_ 2416766549 S2P_Lmt4_Over_DeltUcell1_21 "单体压差过大1级告警阈值";
CM_ SG_ 2416766549 S2P_Lmt4_Over_DeltUcell2_21 "单体压差过大2级告警阈值";
CM_ SG_ 2416766549 S2P_Lmt4_Over_DeltUcell3_21 "单体压差过大3级告警阈值";
CM_ SG_ 2416766549 S2P_Lmt4_Over_DDeltUcell_21 "单体压差过大告警消除回差阈值";
CM_ SG_ 2416766550 S2P_Lmt4_Over_DeltUcell1_22 "单体压差过大1级告警阈值";
CM_ SG_ 2416766550 S2P_Lmt4_Over_DeltUcell2_22 "单体压差过大2级告警阈值";
CM_ SG_ 2416766550 S2P_Lmt4_Over_DeltUcell3_22 "单体压差过大3级告警阈值";
CM_ SG_ 2416766550 S2P_Lmt4_Over_DDeltUcell_22 "单体压差过大告警消除回差阈值";
CM_ SG_ 2416766551 S2P_Lmt4_Over_DeltUcell1_23 "单体压差过大1级告警阈值";
CM_ SG_ 2416766551 S2P_Lmt4_Over_DeltUcell2_23 "单体压差过大2级告警阈值";
CM_ SG_ 2416766551 S2P_Lmt4_Over_DeltUcell3_23 "单体压差过大3级告警阈值";
CM_ SG_ 2416766551 S2P_Lmt4_Over_DDeltUcell_23 "单体压差过大告警消除回差阈值";
CM_ SG_ 2416766552 S2P_Lmt4_Over_DeltUcell1_24 "单体压差过大1级告警阈值";
CM_ SG_ 2416766552 S2P_Lmt4_Over_DeltUcell2_24 "单体压差过大2级告警阈值";
CM_ SG_ 2416766552 S2P_Lmt4_Over_DeltUcell3_24 "单体压差过大3级告警阈值";
CM_ SG_ 2416766552 S2P_Lmt4_Over_DDeltUcell_24 "单体压差过大告警消除回差阈值";
CM_ SG_ 2416766553 S2P_Lmt4_Over_DeltUcell1_25 "单体压差过大1级告警阈值";
CM_ SG_ 2416766553 S2P_Lmt4_Over_DeltUcell2_25 "单体压差过大2级告警阈值";
CM_ SG_ 2416766553 S2P_Lmt4_Over_DeltUcell3_25 "单体压差过大3级告警阈值";
CM_ SG_ 2416766553 S2P_Lmt4_Over_DDeltUcell_25 "单体压差过大告警消除回差阈值";
CM_ SG_ 2416766554 S2P_Lmt4_Over_DeltUcell1_26 "单体压差过大1级告警阈值";
CM_ SG_ 2416766554 S2P_Lmt4_Over_DeltUcell2_26 "单体压差过大2级告警阈值";
CM_ SG_ 2416766554 S2P_Lmt4_Over_DeltUcell3_26 "单体压差过大3级告警阈值";
CM_ SG_ 2416766554 S2P_Lmt4_Over_DDeltUcell_26 "单体压差过大告警消除回差阈值";
CM_ SG_ 2416766555 S2P_Lmt4_Over_DeltUcell1_27 "单体压差过大1级告警阈值";
CM_ SG_ 2416766555 S2P_Lmt4_Over_DeltUcell2_27 "单体压差过大2级告警阈值";
CM_ SG_ 2416766555 S2P_Lmt4_Over_DeltUcell3_27 "单体压差过大3级告警阈值";
CM_ SG_ 2416766555 S2P_Lmt4_Over_DDeltUcell_27 "单体压差过大告警消除回差阈值";
CM_ SG_ 2416766556 S2P_Lmt4_Over_DeltUcell1_28 "单体压差过大1级告警阈值";
CM_ SG_ 2416766556 S2P_Lmt4_Over_DeltUcell2_28 "单体压差过大2级告警阈值";
CM_ SG_ 2416766556 S2P_Lmt4_Over_DeltUcell3_28 "单体压差过大3级告警阈值";
CM_ SG_ 2416766556 S2P_Lmt4_Over_DDeltUcell_28 "单体压差过大告警消除回差阈值";
CM_ SG_ 2416766557 S2P_Lmt4_Over_DeltUcell1_29 "单体压差过大1级告警阈值";
CM_ SG_ 2416766557 S2P_Lmt4_Over_DeltUcell2_29 "单体压差过大2级告警阈值";
CM_ SG_ 2416766557 S2P_Lmt4_Over_DeltUcell3_29 "单体压差过大3级告警阈值";
CM_ SG_ 2416766557 S2P_Lmt4_Over_DDeltUcell_29 "单体压差过大告警消除回差阈值";
CM_ SG_ 2416766558 S2P_Lmt4_Over_DeltUcell1_30 "单体压差过大1级告警阈值";
CM_ SG_ 2416766558 S2P_Lmt4_Over_DeltUcell2_30 "单体压差过大2级告警阈值";
CM_ SG_ 2416766558 S2P_Lmt4_Over_DeltUcell3_30 "单体压差过大3级告警阈值";
CM_ SG_ 2416766558 S2P_Lmt4_Over_DDeltUcell_30 "单体压差过大告警消除回差阈值";
CM_ SG_ 2416766559 S2P_Lmt4_Over_DeltUcell1_31 "单体压差过大1级告警阈值";
CM_ SG_ 2416766559 S2P_Lmt4_Over_DeltUcell2_31 "单体压差过大2级告警阈值";
CM_ SG_ 2416766559 S2P_Lmt4_Over_DeltUcell3_31 "单体压差过大3级告警阈值";
CM_ SG_ 2416766559 S2P_Lmt4_Over_DDeltUcell_31 "单体压差过大告警消除回差阈值";
CM_ SG_ 2416766560 S2P_Lmt4_Over_DeltUcell1_32 "单体压差过大1级告警阈值";
CM_ SG_ 2416766560 S2P_Lmt4_Over_DeltUcell2_32 "单体压差过大2级告警阈值";
CM_ SG_ 2416766560 S2P_Lmt4_Over_DeltUcell3_32 "单体压差过大3级告警阈值";
CM_ SG_ 2416766560 S2P_Lmt4_Over_DDeltUcell_32 "单体压差过大告警消除回差阈值";
CM_ SG_ 2416766561 S2P_Lmt4_Over_DeltUcell1_33 "单体压差过大1级告警阈值";
CM_ SG_ 2416766561 S2P_Lmt4_Over_DeltUcell2_33 "单体压差过大2级告警阈值";
CM_ SG_ 2416766561 S2P_Lmt4_Over_DeltUcell3_33 "单体压差过大3级告警阈值";
CM_ SG_ 2416766561 S2P_Lmt4_Over_DDeltUcell_33 "单体压差过大告警消除回差阈值";
CM_ SG_ 2416766562 S2P_Lmt4_Over_DeltUcell1_34 "单体压差过大1级告警阈值";
CM_ SG_ 2416766562 S2P_Lmt4_Over_DeltUcell2_34 "单体压差过大2级告警阈值";
CM_ SG_ 2416766562 S2P_Lmt4_Over_DeltUcell3_34 "单体压差过大3级告警阈值";
CM_ SG_ 2416766562 S2P_Lmt4_Over_DDeltUcell_34 "单体压差过大告警消除回差阈值";
CM_ SG_ 2416766563 S2P_Lmt4_Over_DeltUcell1_35 "单体压差过大1级告警阈值";
CM_ SG_ 2416766563 S2P_Lmt4_Over_DeltUcell2_35 "单体压差过大2级告警阈值";
CM_ SG_ 2416766563 S2P_Lmt4_Over_DeltUcell3_35 "单体压差过大3级告警阈值";
CM_ SG_ 2416766563 S2P_Lmt4_Over_DDeltUcell_35 "单体压差过大告警消除回差阈值";
CM_ SG_ 2416766564 S2P_Lmt4_Over_DeltUcell1_36 "单体压差过大1级告警阈值";
CM_ SG_ 2416766564 S2P_Lmt4_Over_DeltUcell2_36 "单体压差过大2级告警阈值";
CM_ SG_ 2416766564 S2P_Lmt4_Over_DeltUcell3_36 "单体压差过大3级告警阈值";
CM_ SG_ 2416766564 S2P_Lmt4_Over_DDeltUcell_36 "单体压差过大告警消除回差阈值";
CM_ SG_ 2416766565 S2P_Lmt4_Over_DeltUcell1_37 "单体压差过大1级告警阈值";
CM_ SG_ 2416766565 S2P_Lmt4_Over_DeltUcell2_37 "单体压差过大2级告警阈值";
CM_ SG_ 2416766565 S2P_Lmt4_Over_DeltUcell3_37 "单体压差过大3级告警阈值";
CM_ SG_ 2416766565 S2P_Lmt4_Over_DDeltUcell_37 "单体压差过大告警消除回差阈值";
CM_ SG_ 2416766566 S2P_Lmt4_Over_DeltUcell1_38 "单体压差过大1级告警阈值";
CM_ SG_ 2416766566 S2P_Lmt4_Over_DeltUcell2_38 "单体压差过大2级告警阈值";
CM_ SG_ 2416766566 S2P_Lmt4_Over_DeltUcell3_38 "单体压差过大3级告警阈值";
CM_ SG_ 2416766566 S2P_Lmt4_Over_DDeltUcell_38 "单体压差过大告警消除回差阈值";
CM_ SG_ 2416766567 S2P_Lmt4_Over_DeltUcell1_39 "单体压差过大1级告警阈值";
CM_ SG_ 2416766567 S2P_Lmt4_Over_DeltUcell2_39 "单体压差过大2级告警阈值";
CM_ SG_ 2416766567 S2P_Lmt4_Over_DeltUcell3_39 "单体压差过大3级告警阈值";
CM_ SG_ 2416766567 S2P_Lmt4_Over_DDeltUcell_39 "单体压差过大告警消除回差阈值";
CM_ SG_ 2416766568 S2P_Lmt4_Over_DeltUcell1_40 "单体压差过大1级告警阈值";
CM_ SG_ 2416766568 S2P_Lmt4_Over_DeltUcell2_40 "单体压差过大2级告警阈值";
CM_ SG_ 2416766568 S2P_Lmt4_Over_DeltUcell3_40 "单体压差过大3级告警阈值";
CM_ SG_ 2416766568 S2P_Lmt4_Over_DDeltUcell_40 "单体压差过大告警消除回差阈值";
CM_ SG_ 2416766569 S2P_Lmt4_Over_DeltUcell1_41 "单体压差过大1级告警阈值";
CM_ SG_ 2416766569 S2P_Lmt4_Over_DeltUcell2_41 "单体压差过大2级告警阈值";
CM_ SG_ 2416766569 S2P_Lmt4_Over_DeltUcell3_41 "单体压差过大3级告警阈值";
CM_ SG_ 2416766569 S2P_Lmt4_Over_DDeltUcell_41 "单体压差过大告警消除回差阈值";
CM_ SG_ 2416766570 S2P_Lmt4_Over_DeltUcell1_42 "单体压差过大1级告警阈值";
CM_ SG_ 2416766570 S2P_Lmt4_Over_DeltUcell2_42 "单体压差过大2级告警阈值";
CM_ SG_ 2416766570 S2P_Lmt4_Over_DeltUcell3_42 "单体压差过大3级告警阈值";
CM_ SG_ 2416766570 S2P_Lmt4_Over_DDeltUcell_42 "单体压差过大告警消除回差阈值";
CM_ SG_ 2416766571 S2P_Lmt4_Over_DeltUcell1_43 "单体压差过大1级告警阈值";
CM_ SG_ 2416766571 S2P_Lmt4_Over_DeltUcell2_43 "单体压差过大2级告警阈值";
CM_ SG_ 2416766571 S2P_Lmt4_Over_DeltUcell3_43 "单体压差过大3级告警阈值";
CM_ SG_ 2416766571 S2P_Lmt4_Over_DDeltUcell_43 "单体压差过大告警消除回差阈值";
CM_ SG_ 2416766572 S2P_Lmt4_Over_DeltUcell1_44 "单体压差过大1级告警阈值";
CM_ SG_ 2416766572 S2P_Lmt4_Over_DeltUcell2_44 "单体压差过大2级告警阈值";
CM_ SG_ 2416766572 S2P_Lmt4_Over_DeltUcell3_44 "单体压差过大3级告警阈值";
CM_ SG_ 2416766572 S2P_Lmt4_Over_DDeltUcell_44 "单体压差过大告警消除回差阈值";
CM_ SG_ 2416766573 S2P_Lmt4_Over_DeltUcell1_45 "单体压差过大1级告警阈值";
CM_ SG_ 2416766573 S2P_Lmt4_Over_DeltUcell2_45 "单体压差过大2级告警阈值";
CM_ SG_ 2416766573 S2P_Lmt4_Over_DeltUcell3_45 "单体压差过大3级告警阈值";
CM_ SG_ 2416766573 S2P_Lmt4_Over_DDeltUcell_45 "单体压差过大告警消除回差阈值";
CM_ SG_ 2416766574 S2P_Lmt4_Over_DeltUcell1_46 "单体压差过大1级告警阈值";
CM_ SG_ 2416766574 S2P_Lmt4_Over_DeltUcell2_46 "单体压差过大2级告警阈值";
CM_ SG_ 2416766574 S2P_Lmt4_Over_DeltUcell3_46 "单体压差过大3级告警阈值";
CM_ SG_ 2416766574 S2P_Lmt4_Over_DDeltUcell_46 "单体压差过大告警消除回差阈值";
CM_ SG_ 2416766575 S2P_Lmt4_Over_DeltUcell1_47 "单体压差过大1级告警阈值";
CM_ SG_ 2416766575 S2P_Lmt4_Over_DeltUcell2_47 "单体压差过大2级告警阈值";
CM_ SG_ 2416766575 S2P_Lmt4_Over_DeltUcell3_47 "单体压差过大3级告警阈值";
CM_ SG_ 2416766575 S2P_Lmt4_Over_DDeltUcell_47 "单体压差过大告警消除回差阈值";
CM_ SG_ 2416766576 S2P_Lmt4_Over_DeltUcell1_48 "单体压差过大1级告警阈值";
CM_ SG_ 2416766576 S2P_Lmt4_Over_DeltUcell2_48 "单体压差过大2级告警阈值";
CM_ SG_ 2416766576 S2P_Lmt4_Over_DeltUcell3_48 "单体压差过大3级告警阈值";
CM_ SG_ 2416766576 S2P_Lmt4_Over_DDeltUcell_48 "单体压差过大告警消除回差阈值";
CM_ SG_ 2416766577 S2P_Lmt4_Over_DeltUcell1_49 "单体压差过大1级告警阈值";
CM_ SG_ 2416766577 S2P_Lmt4_Over_DeltUcell2_49 "单体压差过大2级告警阈值";
CM_ SG_ 2416766577 S2P_Lmt4_Over_DeltUcell3_49 "单体压差过大3级告警阈值";
CM_ SG_ 2416766577 S2P_Lmt4_Over_DDeltUcell_49 "单体压差过大告警消除回差阈值";
CM_ SG_ 2416766578 S2P_Lmt4_Over_DeltUcell1_50 "单体压差过大1级告警阈值";
CM_ SG_ 2416766578 S2P_Lmt4_Over_DeltUcell2_50 "单体压差过大2级告警阈值";
CM_ SG_ 2416766578 S2P_Lmt4_Over_DeltUcell3_50 "单体压差过大3级告警阈值";
CM_ SG_ 2416766578 S2P_Lmt4_Over_DDeltUcell_50 "单体压差过大告警消除回差阈值";
CM_ SG_ 2416766579 S2P_Lmt4_Over_DeltUcell1_51 "单体压差过大1级告警阈值";
CM_ SG_ 2416766579 S2P_Lmt4_Over_DeltUcell2_51 "单体压差过大2级告警阈值";
CM_ SG_ 2416766579 S2P_Lmt4_Over_DeltUcell3_51 "单体压差过大3级告警阈值";
CM_ SG_ 2416766579 S2P_Lmt4_Over_DDeltUcell_51 "单体压差过大告警消除回差阈值";
CM_ SG_ 2416766580 S2P_Lmt4_Over_DeltUcell1_52 "单体压差过大1级告警阈值";
CM_ SG_ 2416766580 S2P_Lmt4_Over_DeltUcell2_52 "单体压差过大2级告警阈值";
CM_ SG_ 2416766580 S2P_Lmt4_Over_DeltUcell3_52 "单体压差过大3级告警阈值";
CM_ SG_ 2416766580 S2P_Lmt4_Over_DDeltUcell_52 "单体压差过大告警消除回差阈值";
CM_ SG_ 2416766581 S2P_Lmt4_Over_DeltUcell1_53 "单体压差过大1级告警阈值";
CM_ SG_ 2416766581 S2P_Lmt4_Over_DeltUcell2_53 "单体压差过大2级告警阈值";
CM_ SG_ 2416766581 S2P_Lmt4_Over_DeltUcell3_53 "单体压差过大3级告警阈值";
CM_ SG_ 2416766581 S2P_Lmt4_Over_DDeltUcell_53 "单体压差过大告警消除回差阈值";
CM_ SG_ 2416766582 S2P_Lmt4_Over_DeltUcell1_54 "单体压差过大1级告警阈值";
CM_ SG_ 2416766582 S2P_Lmt4_Over_DeltUcell2_54 "单体压差过大2级告警阈值";
CM_ SG_ 2416766582 S2P_Lmt4_Over_DeltUcell3_54 "单体压差过大3级告警阈值";
CM_ SG_ 2416766582 S2P_Lmt4_Over_DDeltUcell_54 "单体压差过大告警消除回差阈值";
CM_ SG_ 2416766583 S2P_Lmt4_Over_DeltUcell1_55 "单体压差过大1级告警阈值";
CM_ SG_ 2416766583 S2P_Lmt4_Over_DeltUcell2_55 "单体压差过大2级告警阈值";
CM_ SG_ 2416766583 S2P_Lmt4_Over_DeltUcell3_55 "单体压差过大3级告警阈值";
CM_ SG_ 2416766583 S2P_Lmt4_Over_DDeltUcell_55 "单体压差过大告警消除回差阈值";
CM_ SG_ 2416766584 S2P_Lmt4_Over_DeltUcell1_56 "单体压差过大1级告警阈值";
CM_ SG_ 2416766584 S2P_Lmt4_Over_DeltUcell2_56 "单体压差过大2级告警阈值";
CM_ SG_ 2416766584 S2P_Lmt4_Over_DeltUcell3_56 "单体压差过大3级告警阈值";
CM_ SG_ 2416766584 S2P_Lmt4_Over_DDeltUcell_56 "单体压差过大告警消除回差阈值";
CM_ SG_ 2416766585 S2P_Lmt4_Over_DeltUcell1_57 "单体压差过大1级告警阈值";
CM_ SG_ 2416766585 S2P_Lmt4_Over_DeltUcell2_57 "单体压差过大2级告警阈值";
CM_ SG_ 2416766585 S2P_Lmt4_Over_DeltUcell3_57 "单体压差过大3级告警阈值";
CM_ SG_ 2416766585 S2P_Lmt4_Over_DDeltUcell_57 "单体压差过大告警消除回差阈值";
CM_ SG_ 2416766586 S2P_Lmt4_Over_DeltUcell1_58 "单体压差过大1级告警阈值";
CM_ SG_ 2416766586 S2P_Lmt4_Over_DeltUcell2_58 "单体压差过大2级告警阈值";
CM_ SG_ 2416766586 S2P_Lmt4_Over_DeltUcell3_58 "单体压差过大3级告警阈值";
CM_ SG_ 2416766586 S2P_Lmt4_Over_DDeltUcell_58 "单体压差过大告警消除回差阈值";
CM_ SG_ 2416766587 S2P_Lmt4_Over_DeltUcell1_59 "单体压差过大1级告警阈值";
CM_ SG_ 2416766587 S2P_Lmt4_Over_DeltUcell2_59 "单体压差过大2级告警阈值";
CM_ SG_ 2416766587 S2P_Lmt4_Over_DeltUcell3_59 "单体压差过大3级告警阈值";
CM_ SG_ 2416766587 S2P_Lmt4_Over_DDeltUcell_59 "单体压差过大告警消除回差阈值";
CM_ SG_ 2416766588 S2P_Lmt4_Over_DeltUcell1_60 "单体压差过大1级告警阈值";
CM_ SG_ 2416766588 S2P_Lmt4_Over_DeltUcell2_60 "单体压差过大2级告警阈值";
CM_ SG_ 2416766588 S2P_Lmt4_Over_DeltUcell3_60 "单体压差过大3级告警阈值";
CM_ SG_ 2416766588 S2P_Lmt4_Over_DDeltUcell_60 "单体压差过大告警消除回差阈值";
CM_ SG_ 2416766589 S2P_Lmt4_Over_DeltUcell1_61 "单体压差过大1级告警阈值";
CM_ SG_ 2416766589 S2P_Lmt4_Over_DeltUcell2_61 "单体压差过大2级告警阈值";
CM_ SG_ 2416766589 S2P_Lmt4_Over_DeltUcell3_61 "单体压差过大3级告警阈值";
CM_ SG_ 2416766589 S2P_Lmt4_Over_DDeltUcell_61 "单体压差过大告警消除回差阈值";
CM_ SG_ 2416766590 S2P_Lmt4_Over_DeltUcell1_62 "单体压差过大1级告警阈值";
CM_ SG_ 2416766590 S2P_Lmt4_Over_DeltUcell2_62 "单体压差过大2级告警阈值";
CM_ SG_ 2416766590 S2P_Lmt4_Over_DeltUcell3_62 "单体压差过大3级告警阈值";
CM_ SG_ 2416766590 S2P_Lmt4_Over_DDeltUcell_62 "单体压差过大告警消除回差阈值";
CM_ SG_ 2416766591 S2P_Lmt4_Over_DeltUcell1_63 "单体压差过大1级告警阈值";
CM_ SG_ 2416766591 S2P_Lmt4_Over_DeltUcell2_63 "单体压差过大2级告警阈值";
CM_ SG_ 2416766591 S2P_Lmt4_Over_DeltUcell3_63 "单体压差过大3级告警阈值";
CM_ SG_ 2416766591 S2P_Lmt4_Over_DDeltUcell_63 "单体压差过大告警消除回差阈值";
CM_ SG_ 2416832065 S2P_Lmt5_Over_Utank1_01 "电池簇充电电压一级报警值";
CM_ SG_ 2416832065 S2P_Lmt5_Over_Utank2_01 "电池簇充电电压二级报警值";
CM_ SG_ 2416832065 S2P_Lmt5_Over_Utank3_01 "电池簇充电电压三级报警值";
CM_ SG_ 2416832065 S2P_Lmt5_Over_DUtank_01 "分柜过压告警消除回差阈值";
CM_ SG_ 2416832066 S2P_Lmt5_Over_Utank1_02 "电池簇充电电压一级报警值";
CM_ SG_ 2416832066 S2P_Lmt5_Over_Utank2_02 "电池簇充电电压二级报警值";
CM_ SG_ 2416832066 S2P_Lmt5_Over_Utank3_02 "电池簇充电电压三级报警值";
CM_ SG_ 2416832066 S2P_Lmt5_Over_DUtank_02 "分柜过压告警消除回差阈值";
CM_ SG_ 2416832067 S2P_Lmt5_Over_Utank1_03 "电池簇充电电压一级报警值";
CM_ SG_ 2416832067 S2P_Lmt5_Over_Utank2_03 "电池簇充电电压二级报警值";
CM_ SG_ 2416832067 S2P_Lmt5_Over_Utank3_03 "电池簇充电电压三级报警值";
CM_ SG_ 2416832067 S2P_Lmt5_Over_DUtank_03 "分柜过压告警消除回差阈值";
CM_ SG_ 2416832068 S2P_Lmt5_Over_Utank1_04 "电池簇充电电压一级报警值";
CM_ SG_ 2416832068 S2P_Lmt5_Over_Utank2_04 "电池簇充电电压二级报警值";
CM_ SG_ 2416832068 S2P_Lmt5_Over_Utank3_04 "电池簇充电电压三级报警值";
CM_ SG_ 2416832068 S2P_Lmt5_Over_DUtank_04 "分柜过压告警消除回差阈值";
CM_ SG_ 2416832069 S2P_Lmt5_Over_Utank1_05 "电池簇充电电压一级报警值";
CM_ SG_ 2416832069 S2P_Lmt5_Over_Utank2_05 "电池簇充电电压二级报警值";
CM_ SG_ 2416832069 S2P_Lmt5_Over_Utank3_05 "电池簇充电电压三级报警值";
CM_ SG_ 2416832069 S2P_Lmt5_Over_DUtank_05 "分柜过压告警消除回差阈值";
CM_ SG_ 2416832070 S2P_Lmt5_Over_Utank1_06 "电池簇充电电压一级报警值";
CM_ SG_ 2416832070 S2P_Lmt5_Over_Utank2_06 "电池簇充电电压二级报警值";
CM_ SG_ 2416832070 S2P_Lmt5_Over_Utank3_06 "电池簇充电电压三级报警值";
CM_ SG_ 2416832070 S2P_Lmt5_Over_DUtank_06 "分柜过压告警消除回差阈值";
CM_ SG_ 2416832071 S2P_Lmt5_Over_Utank1_07 "电池簇充电电压一级报警值";
CM_ SG_ 2416832071 S2P_Lmt5_Over_Utank2_07 "电池簇充电电压二级报警值";
CM_ SG_ 2416832071 S2P_Lmt5_Over_Utank3_07 "电池簇充电电压三级报警值";
CM_ SG_ 2416832071 S2P_Lmt5_Over_DUtank_07 "分柜过压告警消除回差阈值";
CM_ SG_ 2416832072 S2P_Lmt5_Over_Utank1_08 "电池簇充电电压一级报警值";
CM_ SG_ 2416832072 S2P_Lmt5_Over_Utank2_08 "电池簇充电电压二级报警值";
CM_ SG_ 2416832072 S2P_Lmt5_Over_Utank3_08 "电池簇充电电压三级报警值";
CM_ SG_ 2416832072 S2P_Lmt5_Over_DUtank_08 "分柜过压告警消除回差阈值";
CM_ SG_ 2416832073 S2P_Lmt5_Over_Utank1_09 "电池簇充电电压一级报警值";
CM_ SG_ 2416832073 S2P_Lmt5_Over_Utank2_09 "电池簇充电电压二级报警值";
CM_ SG_ 2416832073 S2P_Lmt5_Over_Utank3_09 "电池簇充电电压三级报警值";
CM_ SG_ 2416832073 S2P_Lmt5_Over_DUtank_09 "分柜过压告警消除回差阈值";
CM_ SG_ 2416832074 S2P_Lmt5_Over_Utank1_10 "电池簇充电电压一级报警值";
CM_ SG_ 2416832074 S2P_Lmt5_Over_Utank2_10 "电池簇充电电压二级报警值";
CM_ SG_ 2416832074 S2P_Lmt5_Over_Utank3_10 "电池簇充电电压三级报警值";
CM_ SG_ 2416832074 S2P_Lmt5_Over_DUtank_10 "分柜过压告警消除回差阈值";
CM_ SG_ 2416832075 S2P_Lmt5_Over_Utank1_11 "电池簇充电电压一级报警值";
CM_ SG_ 2416832075 S2P_Lmt5_Over_Utank2_11 "电池簇充电电压二级报警值";
CM_ SG_ 2416832075 S2P_Lmt5_Over_Utank3_11 "电池簇充电电压三级报警值";
CM_ SG_ 2416832075 S2P_Lmt5_Over_DUtank_11 "分柜过压告警消除回差阈值";
CM_ SG_ 2416832076 S2P_Lmt5_Over_Utank1_12 "电池簇充电电压一级报警值";
CM_ SG_ 2416832076 S2P_Lmt5_Over_Utank2_12 "电池簇充电电压二级报警值";
CM_ SG_ 2416832076 S2P_Lmt5_Over_Utank3_12 "电池簇充电电压三级报警值";
CM_ SG_ 2416832076 S2P_Lmt5_Over_DUtank_12 "分柜过压告警消除回差阈值";
CM_ SG_ 2416832077 S2P_Lmt5_Over_Utank1_13 "电池簇充电电压一级报警值";
CM_ SG_ 2416832077 S2P_Lmt5_Over_Utank2_13 "电池簇充电电压二级报警值";
CM_ SG_ 2416832077 S2P_Lmt5_Over_Utank3_13 "电池簇充电电压三级报警值";
CM_ SG_ 2416832077 S2P_Lmt5_Over_DUtank_13 "分柜过压告警消除回差阈值";
CM_ SG_ 2416832078 S2P_Lmt5_Over_Utank1_14 "电池簇充电电压一级报警值";
CM_ SG_ 2416832078 S2P_Lmt5_Over_Utank2_14 "电池簇充电电压二级报警值";
CM_ SG_ 2416832078 S2P_Lmt5_Over_Utank3_14 "电池簇充电电压三级报警值";
CM_ SG_ 2416832078 S2P_Lmt5_Over_DUtank_14 "分柜过压告警消除回差阈值";
CM_ SG_ 2416832079 S2P_Lmt5_Over_Utank1_15 "电池簇充电电压一级报警值";
CM_ SG_ 2416832079 S2P_Lmt5_Over_Utank2_15 "电池簇充电电压二级报警值";
CM_ SG_ 2416832079 S2P_Lmt5_Over_Utank3_15 "电池簇充电电压三级报警值";
CM_ SG_ 2416832079 S2P_Lmt5_Over_DUtank_15 "分柜过压告警消除回差阈值";
CM_ SG_ 2416832080 S2P_Lmt5_Over_Utank1_16 "电池簇充电电压一级报警值";
CM_ SG_ 2416832080 S2P_Lmt5_Over_Utank2_16 "电池簇充电电压二级报警值";
CM_ SG_ 2416832080 S2P_Lmt5_Over_Utank3_16 "电池簇充电电压三级报警值";
CM_ SG_ 2416832080 S2P_Lmt5_Over_DUtank_16 "分柜过压告警消除回差阈值";
CM_ SG_ 2416832081 S2P_Lmt5_Over_Utank1_17 "电池簇充电电压一级报警值";
CM_ SG_ 2416832081 S2P_Lmt5_Over_Utank2_17 "电池簇充电电压二级报警值";
CM_ SG_ 2416832081 S2P_Lmt5_Over_Utank3_17 "电池簇充电电压三级报警值";
CM_ SG_ 2416832081 S2P_Lmt5_Over_DUtank_17 "分柜过压告警消除回差阈值";
CM_ SG_ 2416832082 S2P_Lmt5_Over_Utank1_18 "电池簇充电电压一级报警值";
CM_ SG_ 2416832082 S2P_Lmt5_Over_Utank2_18 "电池簇充电电压二级报警值";
CM_ SG_ 2416832082 S2P_Lmt5_Over_Utank3_18 "电池簇充电电压三级报警值";
CM_ SG_ 2416832082 S2P_Lmt5_Over_DUtank_18 "分柜过压告警消除回差阈值";
CM_ SG_ 2416832083 S2P_Lmt5_Over_Utank1_19 "电池簇充电电压一级报警值";
CM_ SG_ 2416832083 S2P_Lmt5_Over_Utank2_19 "电池簇充电电压二级报警值";
CM_ SG_ 2416832083 S2P_Lmt5_Over_Utank3_19 "电池簇充电电压三级报警值";
CM_ SG_ 2416832083 S2P_Lmt5_Over_DUtank_19 "分柜过压告警消除回差阈值";
CM_ SG_ 2416832084 S2P_Lmt5_Over_Utank1_20 "电池簇充电电压一级报警值";
CM_ SG_ 2416832084 S2P_Lmt5_Over_Utank2_20 "电池簇充电电压二级报警值";
CM_ SG_ 2416832084 S2P_Lmt5_Over_Utank3_20 "电池簇充电电压三级报警值";
CM_ SG_ 2416832084 S2P_Lmt5_Over_DUtank_20 "分柜过压告警消除回差阈值";
CM_ SG_ 2416832085 S2P_Lmt5_Over_Utank1_21 "电池簇充电电压一级报警值";
CM_ SG_ 2416832085 S2P_Lmt5_Over_Utank2_21 "电池簇充电电压二级报警值";
CM_ SG_ 2416832085 S2P_Lmt5_Over_Utank3_21 "电池簇充电电压三级报警值";
CM_ SG_ 2416832085 S2P_Lmt5_Over_DUtank_21 "分柜过压告警消除回差阈值";
CM_ SG_ 2416832086 S2P_Lmt5_Over_Utank1_22 "电池簇充电电压一级报警值";
CM_ SG_ 2416832086 S2P_Lmt5_Over_Utank2_22 "电池簇充电电压二级报警值";
CM_ SG_ 2416832086 S2P_Lmt5_Over_Utank3_22 "电池簇充电电压三级报警值";
CM_ SG_ 2416832086 S2P_Lmt5_Over_DUtank_22 "分柜过压告警消除回差阈值";
CM_ SG_ 2416832087 S2P_Lmt5_Over_Utank1_23 "电池簇充电电压一级报警值";
CM_ SG_ 2416832087 S2P_Lmt5_Over_Utank2_23 "电池簇充电电压二级报警值";
CM_ SG_ 2416832087 S2P_Lmt5_Over_Utank3_23 "电池簇充电电压三级报警值";
CM_ SG_ 2416832087 S2P_Lmt5_Over_DUtank_23 "分柜过压告警消除回差阈值";
CM_ SG_ 2416832088 S2P_Lmt5_Over_Utank1_24 "电池簇充电电压一级报警值";
CM_ SG_ 2416832088 S2P_Lmt5_Over_Utank2_24 "电池簇充电电压二级报警值";
CM_ SG_ 2416832088 S2P_Lmt5_Over_Utank3_24 "电池簇充电电压三级报警值";
CM_ SG_ 2416832088 S2P_Lmt5_Over_DUtank_24 "分柜过压告警消除回差阈值";
CM_ SG_ 2416832089 S2P_Lmt5_Over_Utank1_25 "电池簇充电电压一级报警值";
CM_ SG_ 2416832089 S2P_Lmt5_Over_Utank2_25 "电池簇充电电压二级报警值";
CM_ SG_ 2416832089 S2P_Lmt5_Over_Utank3_25 "电池簇充电电压三级报警值";
CM_ SG_ 2416832089 S2P_Lmt5_Over_DUtank_25 "分柜过压告警消除回差阈值";
CM_ SG_ 2416832090 S2P_Lmt5_Over_Utank1_26 "电池簇充电电压一级报警值";
CM_ SG_ 2416832090 S2P_Lmt5_Over_Utank2_26 "电池簇充电电压二级报警值";
CM_ SG_ 2416832090 S2P_Lmt5_Over_Utank3_26 "电池簇充电电压三级报警值";
CM_ SG_ 2416832090 S2P_Lmt5_Over_DUtank_26 "分柜过压告警消除回差阈值";
CM_ SG_ 2416832091 S2P_Lmt5_Over_Utank1_27 "电池簇充电电压一级报警值";
CM_ SG_ 2416832091 S2P_Lmt5_Over_Utank2_27 "电池簇充电电压二级报警值";
CM_ SG_ 2416832091 S2P_Lmt5_Over_Utank3_27 "电池簇充电电压三级报警值";
CM_ SG_ 2416832091 S2P_Lmt5_Over_DUtank_27 "分柜过压告警消除回差阈值";
CM_ SG_ 2416832092 S2P_Lmt5_Over_Utank1_28 "电池簇充电电压一级报警值";
CM_ SG_ 2416832092 S2P_Lmt5_Over_Utank2_28 "电池簇充电电压二级报警值";
CM_ SG_ 2416832092 S2P_Lmt5_Over_Utank3_28 "电池簇充电电压三级报警值";
CM_ SG_ 2416832092 S2P_Lmt5_Over_DUtank_28 "分柜过压告警消除回差阈值";
CM_ SG_ 2416832093 S2P_Lmt5_Over_Utank1_29 "电池簇充电电压一级报警值";
CM_ SG_ 2416832093 S2P_Lmt5_Over_Utank2_29 "电池簇充电电压二级报警值";
CM_ SG_ 2416832093 S2P_Lmt5_Over_Utank3_29 "电池簇充电电压三级报警值";
CM_ SG_ 2416832093 S2P_Lmt5_Over_DUtank_29 "分柜过压告警消除回差阈值";
CM_ SG_ 2416832094 S2P_Lmt5_Over_Utank1_30 "电池簇充电电压一级报警值";
CM_ SG_ 2416832094 S2P_Lmt5_Over_Utank2_30 "电池簇充电电压二级报警值";
CM_ SG_ 2416832094 S2P_Lmt5_Over_Utank3_30 "电池簇充电电压三级报警值";
CM_ SG_ 2416832094 S2P_Lmt5_Over_DUtank_30 "分柜过压告警消除回差阈值";
CM_ SG_ 2416832095 S2P_Lmt5_Over_Utank1_31 "电池簇充电电压一级报警值";
CM_ SG_ 2416832095 S2P_Lmt5_Over_Utank2_31 "电池簇充电电压二级报警值";
CM_ SG_ 2416832095 S2P_Lmt5_Over_Utank3_31 "电池簇充电电压三级报警值";
CM_ SG_ 2416832095 S2P_Lmt5_Over_DUtank_31 "分柜过压告警消除回差阈值";
CM_ SG_ 2416832096 S2P_Lmt5_Over_Utank1_32 "电池簇充电电压一级报警值";
CM_ SG_ 2416832096 S2P_Lmt5_Over_Utank2_32 "电池簇充电电压二级报警值";
CM_ SG_ 2416832096 S2P_Lmt5_Over_Utank3_32 "电池簇充电电压三级报警值";
CM_ SG_ 2416832096 S2P_Lmt5_Over_DUtank_32 "分柜过压告警消除回差阈值";
CM_ SG_ 2416832097 S2P_Lmt5_Over_Utank1_33 "电池簇充电电压一级报警值";
CM_ SG_ 2416832097 S2P_Lmt5_Over_Utank2_33 "电池簇充电电压二级报警值";
CM_ SG_ 2416832097 S2P_Lmt5_Over_Utank3_33 "电池簇充电电压三级报警值";
CM_ SG_ 2416832097 S2P_Lmt5_Over_DUtank_33 "分柜过压告警消除回差阈值";
CM_ SG_ 2416832098 S2P_Lmt5_Over_Utank1_34 "电池簇充电电压一级报警值";
CM_ SG_ 2416832098 S2P_Lmt5_Over_Utank2_34 "电池簇充电电压二级报警值";
CM_ SG_ 2416832098 S2P_Lmt5_Over_Utank3_34 "电池簇充电电压三级报警值";
CM_ SG_ 2416832098 S2P_Lmt5_Over_DUtank_34 "分柜过压告警消除回差阈值";
CM_ SG_ 2416832099 S2P_Lmt5_Over_Utank1_35 "电池簇充电电压一级报警值";
CM_ SG_ 2416832099 S2P_Lmt5_Over_Utank2_35 "电池簇充电电压二级报警值";
CM_ SG_ 2416832099 S2P_Lmt5_Over_Utank3_35 "电池簇充电电压三级报警值";
CM_ SG_ 2416832099 S2P_Lmt5_Over_DUtank_35 "分柜过压告警消除回差阈值";
CM_ SG_ 2416832100 S2P_Lmt5_Over_Utank1_36 "电池簇充电电压一级报警值";
CM_ SG_ 2416832100 S2P_Lmt5_Over_Utank2_36 "电池簇充电电压二级报警值";
CM_ SG_ 2416832100 S2P_Lmt5_Over_Utank3_36 "电池簇充电电压三级报警值";
CM_ SG_ 2416832100 S2P_Lmt5_Over_DUtank_36 "分柜过压告警消除回差阈值";
CM_ SG_ 2416832101 S2P_Lmt5_Over_Utank1_37 "电池簇充电电压一级报警值";
CM_ SG_ 2416832101 S2P_Lmt5_Over_Utank2_37 "电池簇充电电压二级报警值";
CM_ SG_ 2416832101 S2P_Lmt5_Over_Utank3_37 "电池簇充电电压三级报警值";
CM_ SG_ 2416832101 S2P_Lmt5_Over_DUtank_37 "分柜过压告警消除回差阈值";
CM_ SG_ 2416832102 S2P_Lmt5_Over_Utank1_38 "电池簇充电电压一级报警值";
CM_ SG_ 2416832102 S2P_Lmt5_Over_Utank2_38 "电池簇充电电压二级报警值";
CM_ SG_ 2416832102 S2P_Lmt5_Over_Utank3_38 "电池簇充电电压三级报警值";
CM_ SG_ 2416832102 S2P_Lmt5_Over_DUtank_38 "分柜过压告警消除回差阈值";
CM_ SG_ 2416832103 S2P_Lmt5_Over_Utank1_39 "电池簇充电电压一级报警值";
CM_ SG_ 2416832103 S2P_Lmt5_Over_Utank2_39 "电池簇充电电压二级报警值";
CM_ SG_ 2416832103 S2P_Lmt5_Over_Utank3_39 "电池簇充电电压三级报警值";
CM_ SG_ 2416832103 S2P_Lmt5_Over_DUtank_39 "分柜过压告警消除回差阈值";
CM_ SG_ 2416832104 S2P_Lmt5_Over_Utank1_40 "电池簇充电电压一级报警值";
CM_ SG_ 2416832104 S2P_Lmt5_Over_Utank2_40 "电池簇充电电压二级报警值";
CM_ SG_ 2416832104 S2P_Lmt5_Over_Utank3_40 "电池簇充电电压三级报警值";
CM_ SG_ 2416832104 S2P_Lmt5_Over_DUtank_40 "分柜过压告警消除回差阈值";
CM_ SG_ 2416832105 S2P_Lmt5_Over_Utank1_41 "电池簇充电电压一级报警值";
CM_ SG_ 2416832105 S2P_Lmt5_Over_Utank2_41 "电池簇充电电压二级报警值";
CM_ SG_ 2416832105 S2P_Lmt5_Over_Utank3_41 "电池簇充电电压三级报警值";
CM_ SG_ 2416832105 S2P_Lmt5_Over_DUtank_41 "分柜过压告警消除回差阈值";
CM_ SG_ 2416832106 S2P_Lmt5_Over_Utank1_42 "电池簇充电电压一级报警值";
CM_ SG_ 2416832106 S2P_Lmt5_Over_Utank2_42 "电池簇充电电压二级报警值";
CM_ SG_ 2416832106 S2P_Lmt5_Over_Utank3_42 "电池簇充电电压三级报警值";
CM_ SG_ 2416832106 S2P_Lmt5_Over_DUtank_42 "分柜过压告警消除回差阈值";
CM_ SG_ 2416832107 S2P_Lmt5_Over_Utank1_43 "电池簇充电电压一级报警值";
CM_ SG_ 2416832107 S2P_Lmt5_Over_Utank2_43 "电池簇充电电压二级报警值";
CM_ SG_ 2416832107 S2P_Lmt5_Over_Utank3_43 "电池簇充电电压三级报警值";
CM_ SG_ 2416832107 S2P_Lmt5_Over_DUtank_43 "分柜过压告警消除回差阈值";
CM_ SG_ 2416832108 S2P_Lmt5_Over_Utank1_44 "电池簇充电电压一级报警值";
CM_ SG_ 2416832108 S2P_Lmt5_Over_Utank2_44 "电池簇充电电压二级报警值";
CM_ SG_ 2416832108 S2P_Lmt5_Over_Utank3_44 "电池簇充电电压三级报警值";
CM_ SG_ 2416832108 S2P_Lmt5_Over_DUtank_44 "分柜过压告警消除回差阈值";
CM_ SG_ 2416832109 S2P_Lmt5_Over_Utank1_45 "电池簇充电电压一级报警值";
CM_ SG_ 2416832109 S2P_Lmt5_Over_Utank2_45 "电池簇充电电压二级报警值";
CM_ SG_ 2416832109 S2P_Lmt5_Over_Utank3_45 "电池簇充电电压三级报警值";
CM_ SG_ 2416832109 S2P_Lmt5_Over_DUtank_45 "分柜过压告警消除回差阈值";
CM_ SG_ 2416832110 S2P_Lmt5_Over_Utank1_46 "电池簇充电电压一级报警值";
CM_ SG_ 2416832110 S2P_Lmt5_Over_Utank2_46 "电池簇充电电压二级报警值";
CM_ SG_ 2416832110 S2P_Lmt5_Over_Utank3_46 "电池簇充电电压三级报警值";
CM_ SG_ 2416832110 S2P_Lmt5_Over_DUtank_46 "分柜过压告警消除回差阈值";
CM_ SG_ 2416832111 S2P_Lmt5_Over_Utank1_47 "电池簇充电电压一级报警值";
CM_ SG_ 2416832111 S2P_Lmt5_Over_Utank2_47 "电池簇充电电压二级报警值";
CM_ SG_ 2416832111 S2P_Lmt5_Over_Utank3_47 "电池簇充电电压三级报警值";
CM_ SG_ 2416832111 S2P_Lmt5_Over_DUtank_47 "分柜过压告警消除回差阈值";
CM_ SG_ 2416832112 S2P_Lmt5_Over_Utank1_48 "电池簇充电电压一级报警值";
CM_ SG_ 2416832112 S2P_Lmt5_Over_Utank2_48 "电池簇充电电压二级报警值";
CM_ SG_ 2416832112 S2P_Lmt5_Over_Utank3_48 "电池簇充电电压三级报警值";
CM_ SG_ 2416832112 S2P_Lmt5_Over_DUtank_48 "分柜过压告警消除回差阈值";
CM_ SG_ 2416832113 S2P_Lmt5_Over_Utank1_49 "电池簇充电电压一级报警值";
CM_ SG_ 2416832113 S2P_Lmt5_Over_Utank2_49 "电池簇充电电压二级报警值";
CM_ SG_ 2416832113 S2P_Lmt5_Over_Utank3_49 "电池簇充电电压三级报警值";
CM_ SG_ 2416832113 S2P_Lmt5_Over_DUtank_49 "分柜过压告警消除回差阈值";
CM_ SG_ 2416832114 S2P_Lmt5_Over_Utank1_50 "电池簇充电电压一级报警值";
CM_ SG_ 2416832114 S2P_Lmt5_Over_Utank2_50 "电池簇充电电压二级报警值";
CM_ SG_ 2416832114 S2P_Lmt5_Over_Utank3_50 "电池簇充电电压三级报警值";
CM_ SG_ 2416832114 S2P_Lmt5_Over_DUtank_50 "分柜过压告警消除回差阈值";
CM_ SG_ 2416832115 S2P_Lmt5_Over_Utank1_51 "电池簇充电电压一级报警值";
CM_ SG_ 2416832115 S2P_Lmt5_Over_Utank2_51 "电池簇充电电压二级报警值";
CM_ SG_ 2416832115 S2P_Lmt5_Over_Utank3_51 "电池簇充电电压三级报警值";
CM_ SG_ 2416832115 S2P_Lmt5_Over_DUtank_51 "分柜过压告警消除回差阈值";
CM_ SG_ 2416832116 S2P_Lmt5_Over_Utank1_52 "电池簇充电电压一级报警值";
CM_ SG_ 2416832116 S2P_Lmt5_Over_Utank2_52 "电池簇充电电压二级报警值";
CM_ SG_ 2416832116 S2P_Lmt5_Over_Utank3_52 "电池簇充电电压三级报警值";
CM_ SG_ 2416832116 S2P_Lmt5_Over_DUtank_52 "分柜过压告警消除回差阈值";
CM_ SG_ 2416832117 S2P_Lmt5_Over_Utank1_53 "电池簇充电电压一级报警值";
CM_ SG_ 2416832117 S2P_Lmt5_Over_Utank2_53 "电池簇充电电压二级报警值";
CM_ SG_ 2416832117 S2P_Lmt5_Over_Utank3_53 "电池簇充电电压三级报警值";
CM_ SG_ 2416832117 S2P_Lmt5_Over_DUtank_53 "分柜过压告警消除回差阈值";
CM_ SG_ 2416832118 S2P_Lmt5_Over_Utank1_54 "电池簇充电电压一级报警值";
CM_ SG_ 2416832118 S2P_Lmt5_Over_Utank2_54 "电池簇充电电压二级报警值";
CM_ SG_ 2416832118 S2P_Lmt5_Over_Utank3_54 "电池簇充电电压三级报警值";
CM_ SG_ 2416832118 S2P_Lmt5_Over_DUtank_54 "分柜过压告警消除回差阈值";
CM_ SG_ 2416832119 S2P_Lmt5_Over_Utank1_55 "电池簇充电电压一级报警值";
CM_ SG_ 2416832119 S2P_Lmt5_Over_Utank2_55 "电池簇充电电压二级报警值";
CM_ SG_ 2416832119 S2P_Lmt5_Over_Utank3_55 "电池簇充电电压三级报警值";
CM_ SG_ 2416832119 S2P_Lmt5_Over_DUtank_55 "分柜过压告警消除回差阈值";
CM_ SG_ 2416832120 S2P_Lmt5_Over_Utank1_56 "电池簇充电电压一级报警值";
CM_ SG_ 2416832120 S2P_Lmt5_Over_Utank2_56 "电池簇充电电压二级报警值";
CM_ SG_ 2416832120 S2P_Lmt5_Over_Utank3_56 "电池簇充电电压三级报警值";
CM_ SG_ 2416832120 S2P_Lmt5_Over_DUtank_56 "分柜过压告警消除回差阈值";
CM_ SG_ 2416832121 S2P_Lmt5_Over_Utank1_57 "电池簇充电电压一级报警值";
CM_ SG_ 2416832121 S2P_Lmt5_Over_Utank2_57 "电池簇充电电压二级报警值";
CM_ SG_ 2416832121 S2P_Lmt5_Over_Utank3_57 "电池簇充电电压三级报警值";
CM_ SG_ 2416832121 S2P_Lmt5_Over_DUtank_57 "分柜过压告警消除回差阈值";
CM_ SG_ 2416832122 S2P_Lmt5_Over_Utank1_58 "电池簇充电电压一级报警值";
CM_ SG_ 2416832122 S2P_Lmt5_Over_Utank2_58 "电池簇充电电压二级报警值";
CM_ SG_ 2416832122 S2P_Lmt5_Over_Utank3_58 "电池簇充电电压三级报警值";
CM_ SG_ 2416832122 S2P_Lmt5_Over_DUtank_58 "分柜过压告警消除回差阈值";
CM_ SG_ 2416832123 S2P_Lmt5_Over_Utank1_59 "电池簇充电电压一级报警值";
CM_ SG_ 2416832123 S2P_Lmt5_Over_Utank2_59 "电池簇充电电压二级报警值";
CM_ SG_ 2416832123 S2P_Lmt5_Over_Utank3_59 "电池簇充电电压三级报警值";
CM_ SG_ 2416832123 S2P_Lmt5_Over_DUtank_59 "分柜过压告警消除回差阈值";
CM_ SG_ 2416832124 S2P_Lmt5_Over_Utank1_60 "电池簇充电电压一级报警值";
CM_ SG_ 2416832124 S2P_Lmt5_Over_Utank2_60 "电池簇充电电压二级报警值";
CM_ SG_ 2416832124 S2P_Lmt5_Over_Utank3_60 "电池簇充电电压三级报警值";
CM_ SG_ 2416832124 S2P_Lmt5_Over_DUtank_60 "分柜过压告警消除回差阈值";
CM_ SG_ 2416832125 S2P_Lmt5_Over_Utank1_61 "电池簇充电电压一级报警值";
CM_ SG_ 2416832125 S2P_Lmt5_Over_Utank2_61 "电池簇充电电压二级报警值";
CM_ SG_ 2416832125 S2P_Lmt5_Over_Utank3_61 "电池簇充电电压三级报警值";
CM_ SG_ 2416832125 S2P_Lmt5_Over_DUtank_61 "分柜过压告警消除回差阈值";
CM_ SG_ 2416832126 S2P_Lmt5_Over_Utank1_62 "电池簇充电电压一级报警值";
CM_ SG_ 2416832126 S2P_Lmt5_Over_Utank2_62 "电池簇充电电压二级报警值";
CM_ SG_ 2416832126 S2P_Lmt5_Over_Utank3_62 "电池簇充电电压三级报警值";
CM_ SG_ 2416832126 S2P_Lmt5_Over_DUtank_62 "分柜过压告警消除回差阈值";
CM_ SG_ 2416832127 S2P_Lmt5_Over_Utank1_63 "电池簇充电电压一级报警值";
CM_ SG_ 2416832127 S2P_Lmt5_Over_Utank2_63 "电池簇充电电压二级报警值";
CM_ SG_ 2416832127 S2P_Lmt5_Over_Utank3_63 "电池簇充电电压三级报警值";
CM_ SG_ 2416832127 S2P_Lmt5_Over_DUtank_63 "分柜过压告警消除回差阈值";
CM_ SG_ 2416897601 S2P_Lmt6_Under_Utank1_01 "电池簇放电电压一级报警值";
CM_ SG_ 2416897601 S2P_Lmt6_Under_Utank2_01 "电池簇放电电压二级报警值";
CM_ SG_ 2416897601 S2P_Lmt6_Under_Utank3_01 "电池簇放电电压三级报警值";
CM_ SG_ 2416897601 S2P_Lmt6_Under_DUtank_01 "分柜欠压告警消除回差阈值";
CM_ SG_ 2416897602 S2P_Lmt6_Under_Utank1_02 "电池簇放电电压一级报警值";
CM_ SG_ 2416897602 S2P_Lmt6_Under_Utank2_02 "电池簇放电电压二级报警值";
CM_ SG_ 2416897602 S2P_Lmt6_Under_Utank3_02 "电池簇放电电压三级报警值";
CM_ SG_ 2416897602 S2P_Lmt6_Under_DUtank_02 "分柜欠压告警消除回差阈值";
CM_ SG_ 2416897603 S2P_Lmt6_Under_Utank1_03 "电池簇放电电压一级报警值";
CM_ SG_ 2416897603 S2P_Lmt6_Under_Utank2_03 "电池簇放电电压二级报警值";
CM_ SG_ 2416897603 S2P_Lmt6_Under_Utank3_03 "电池簇放电电压三级报警值";
CM_ SG_ 2416897603 S2P_Lmt6_Under_DUtank_03 "分柜欠压告警消除回差阈值";
CM_ SG_ 2416897604 S2P_Lmt6_Under_Utank1_04 "电池簇放电电压一级报警值";
CM_ SG_ 2416897604 S2P_Lmt6_Under_Utank2_04 "电池簇放电电压二级报警值";
CM_ SG_ 2416897604 S2P_Lmt6_Under_Utank3_04 "电池簇放电电压三级报警值";
CM_ SG_ 2416897604 S2P_Lmt6_Under_DUtank_04 "分柜欠压告警消除回差阈值";
CM_ SG_ 2416897605 S2P_Lmt6_Under_Utank1_05 "电池簇放电电压一级报警值";
CM_ SG_ 2416897605 S2P_Lmt6_Under_Utank2_05 "电池簇放电电压二级报警值";
CM_ SG_ 2416897605 S2P_Lmt6_Under_Utank3_05 "电池簇放电电压三级报警值";
CM_ SG_ 2416897605 S2P_Lmt6_Under_DUtank_05 "分柜欠压告警消除回差阈值";
CM_ SG_ 2416897606 S2P_Lmt6_Under_Utank1_06 "电池簇放电电压一级报警值";
CM_ SG_ 2416897606 S2P_Lmt6_Under_Utank2_06 "电池簇放电电压二级报警值";
CM_ SG_ 2416897606 S2P_Lmt6_Under_Utank3_06 "电池簇放电电压三级报警值";
CM_ SG_ 2416897606 S2P_Lmt6_Under_DUtank_06 "分柜欠压告警消除回差阈值";
CM_ SG_ 2416897607 S2P_Lmt6_Under_Utank1_07 "电池簇放电电压一级报警值";
CM_ SG_ 2416897607 S2P_Lmt6_Under_Utank2_07 "电池簇放电电压二级报警值";
CM_ SG_ 2416897607 S2P_Lmt6_Under_Utank3_07 "电池簇放电电压三级报警值";
CM_ SG_ 2416897607 S2P_Lmt6_Under_DUtank_07 "分柜欠压告警消除回差阈值";
VERSION ""

NS_ :

BS_:

BU_: MBMU PC SBMU IMM ETH DCDC LEMS

BO_ 2416897608 S2P_Lmt6__08: 8 SBMU
 SG_ S2P_Lmt6_Under_Utank1_08 : 0|16@1+ (0.1,0) [0|6553.5] "V"  PC
 SG_ S2P_Lmt6_Under_Utank2_08 : 16|16@1+ (0.1,0) [0|6553.5] "V"  PC
 SG_ S2P_Lmt6_Under_Utank3_08 : 32|16@1+ (0.1,0) [0|6553.5] "V"  PC
 SG_ S2P_Lmt6_Under_DUtank_08 : 48|16@1+ (0.1,0) [0|6553.5] "V"  PC

BO_ 2416897609 S2P_Lmt6__09: 8 SBMU
 SG_ S2P_Lmt6_Under_Utank1_09 : 0|16@1+ (0.1,0) [0|6553.5] "V"  PC
 SG_ S2P_Lmt6_Under_Utank2_09 : 16|16@1+ (0.1,0) [0|6553.5] "V"  PC
 SG_ S2P_Lmt6_Under_Utank3_09 : 32|16@1+ (0.1,0) [0|6553.5] "V"  PC
 SG_ S2P_Lmt6_Under_DUtank_09 : 48|16@1+ (0.1,0) [0|6553.5] "V"  PC

BO_ 2416897610 S2P_Lmt6__10: 8 SBMU
 SG_ S2P_Lmt6_Under_Utank1_10 : 0|16@1+ (0.1,0) [0|6553.5] "V"  PC
 SG_ S2P_Lmt6_Under_Utank2_10 : 16|16@1+ (0.1,0) [0|6553.5] "V"  PC
 SG_ S2P_Lmt6_Under_Utank3_10 : 32|16@1+ (0.1,0) [0|6553.5] "V"  PC
 SG_ S2P_Lmt6_Under_DUtank_10 : 48|16@1+ (0.1,0) [0|6553.5] "V"  PC

BO_ 2416897611 S2P_Lmt6__11: 8 SBMU
 SG_ S2P_Lmt6_Under_Utank1_11 : 0|16@1+ (0.1,0) [0|6553.5] "V"  PC
 SG_ S2P_Lmt6_Under_Utank2_11 : 16|16@1+ (0.1,0) [0|6553.5] "V"  PC
 SG_ S2P_Lmt6_Under_Utank3_11 : 32|16@1+ (0.1,0) [0|6553.5] "V"  PC
 SG_ S2P_Lmt6_Under_DUtank_11 : 48|16@1+ (0.1,0) [0|6553.5] "V"  PC

BO_ 2416897612 S2P_Lmt6__12: 8 SBMU
 SG_ S2P_Lmt6_Under_Utank1_12 : 0|16@1+ (0.1,0) [0|6553.5] "V"  PC
 SG_ S2P_Lmt6_Under_Utank2_12 : 16|16@1+ (0.1,0) [0|6553.5] "V"  PC
 SG_ S2P_Lmt6_Under_Utank3_12 : 32|16@1+ (0.1,0) [0|6553.5] "V"  PC
 SG_ S2P_Lmt6_Under_DUtank_12 : 48|16@1+ (0.1,0) [0|6553.5] "V"  PC

BO_ 2416897613 S2P_Lmt6__13: 8 SBMU
 SG_ S2P_Lmt6_Under_Utank1_13 : 0|16@1+ (0.1,0) [0|6553.5] "V"  PC
 SG_ S2P_Lmt6_Under_Utank2_13 : 16|16@1+ (0.1,0) [0|6553.5] "V"  PC
 SG_ S2P_Lmt6_Under_Utank3_13 : 32|16@1+ (0.1,0) [0|6553.5] "V"  PC
 SG_ S2P_Lmt6_Under_DUtank_13 : 48|16@1+ (0.1,0) [0|6553.5] "V"  PC

BO_ 2416897614 S2P_Lmt6__14: 8 SBMU
 SG_ S2P_Lmt6_Under_Utank1_14 : 0|16@1+ (0.1,0) [0|6553.5] "V"  PC
 SG_ S2P_Lmt6_Under_Utank2_14 : 16|16@1+ (0.1,0) [0|6553.5] "V"  PC
 SG_ S2P_Lmt6_Under_Utank3_14 : 32|16@1+ (0.1,0) [0|6553.5] "V"  PC
 SG_ S2P_Lmt6_Under_DUtank_14 : 48|16@1+ (0.1,0) [0|6553.5] "V"  PC

BO_ 2416897615 S2P_Lmt6__15: 8 SBMU
 SG_ S2P_Lmt6_Under_Utank1_15 : 0|16@1+ (0.1,0) [0|6553.5] "V"  PC
 SG_ S2P_Lmt6_Under_Utank2_15 : 16|16@1+ (0.1,0) [0|6553.5] "V"  PC
 SG_ S2P_Lmt6_Under_Utank3_15 : 32|16@1+ (0.1,0) [0|6553.5] "V"  PC
 SG_ S2P_Lmt6_Under_DUtank_15 : 48|16@1+ (0.1,0) [0|6553.5] "V"  PC

BO_ 2416897616 S2P_Lmt6__16: 8 SBMU
 SG_ S2P_Lmt6_Under_Utank1_16 : 0|16@1+ (0.1,0) [0|6553.5] "V"  PC
 SG_ S2P_Lmt6_Under_Utank2_16 : 16|16@1+ (0.1,0) [0|6553.5] "V"  PC
 SG_ S2P_Lmt6_Under_Utank3_16 : 32|16@1+ (0.1,0) [0|6553.5] "V"  PC
 SG_ S2P_Lmt6_Under_DUtank_16 : 48|16@1+ (0.1,0) [0|6553.5] "V"  PC

BO_ 2416897617 S2P_Lmt6__17: 8 SBMU
 SG_ S2P_Lmt6_Under_Utank1_17 : 0|16@1+ (0.1,0) [0|6553.5] "V"  PC
 SG_ S2P_Lmt6_Under_Utank2_17 : 16|16@1+ (0.1,0) [0|6553.5] "V"  PC
 SG_ S2P_Lmt6_Under_Utank3_17 : 32|16@1+ (0.1,0) [0|6553.5] "V"  PC
 SG_ S2P_Lmt6_Under_DUtank_17 : 48|16@1+ (0.1,0) [0|6553.5] "V"  PC

BO_ 2416897618 S2P_Lmt6__18: 8 SBMU
 SG_ S2P_Lmt6_Under_Utank1_18 : 0|16@1+ (0.1,0) [0|6553.5] "V"  PC
 SG_ S2P_Lmt6_Under_Utank2_18 : 16|16@1+ (0.1,0) [0|6553.5] "V"  PC
 SG_ S2P_Lmt6_Under_Utank3_18 : 32|16@1+ (0.1,0) [0|6553.5] "V"  PC
 SG_ S2P_Lmt6_Under_DUtank_18 : 48|16@1+ (0.1,0) [0|6553.5] "V"  PC

BO_ 2416897619 S2P_Lmt6__19: 8 SBMU
 SG_ S2P_Lmt6_Under_Utank1_19 : 0|16@1+ (0.1,0) [0|6553.5] "V"  PC
 SG_ S2P_Lmt6_Under_Utank2_19 : 16|16@1+ (0.1,0) [0|6553.5] "V"  PC
 SG_ S2P_Lmt6_Under_Utank3_19 : 32|16@1+ (0.1,0) [0|6553.5] "V"  PC
 SG_ S2P_Lmt6_Under_DUtank_19 : 48|16@1+ (0.1,0) [0|6553.5] "V"  PC

BO_ 2416897620 S2P_Lmt6__20: 8 SBMU
 SG_ S2P_Lmt6_Under_Utank1_20 : 0|16@1+ (0.1,0) [0|6553.5] "V"  PC
 SG_ S2P_Lmt6_Under_Utank2_20 : 16|16@1+ (0.1,0) [0|6553.5] "V"  PC
 SG_ S2P_Lmt6_Under_Utank3_20 : 32|16@1+ (0.1,0) [0|6553.5] "V"  PC
 SG_ S2P_Lmt6_Under_DUtank_20 : 48|16@1+ (0.1,0) [0|6553.5] "V"  PC

BO_ 2416897621 S2P_Lmt6__21: 8 SBMU
 SG_ S2P_Lmt6_Under_Utank1_21 : 0|16@1+ (0.1,0) [0|6553.5] "V"  PC
 SG_ S2P_Lmt6_Under_Utank2_21 : 16|16@1+ (0.1,0) [0|6553.5] "V"  PC
 SG_ S2P_Lmt6_Under_Utank3_21 : 32|16@1+ (0.1,0) [0|6553.5] "V"  PC
 SG_ S2P_Lmt6_Under_DUtank_21 : 48|16@1+ (0.1,0) [0|6553.5] "V"  PC

BO_ 2416897622 S2P_Lmt6__22: 8 SBMU
 SG_ S2P_Lmt6_Under_Utank1_22 : 0|16@1+ (0.1,0) [0|6553.5] "V"  PC
 SG_ S2P_Lmt6_Under_Utank2_22 : 16|16@1+ (0.1,0) [0|6553.5] "V"  PC
 SG_ S2P_Lmt6_Under_Utank3_22 : 32|16@1+ (0.1,0) [0|6553.5] "V"  PC
 SG_ S2P_Lmt6_Under_DUtank_22 : 48|16@1+ (0.1,0) [0|6553.5] "V"  PC

BO_ 2416897623 S2P_Lmt6__23: 8 SBMU
 SG_ S2P_Lmt6_Under_Utank1_23 : 0|16@1+ (0.1,0) [0|6553.5] "V"  PC
 SG_ S2P_Lmt6_Under_Utank2_23 : 16|16@1+ (0.1,0) [0|6553.5] "V"  PC
 SG_ S2P_Lmt6_Under_Utank3_23 : 32|16@1+ (0.1,0) [0|6553.5] "V"  PC
 SG_ S2P_Lmt6_Under_DUtank_23 : 48|16@1+ (0.1,0) [0|6553.5] "V"  PC

BO_ 2416897624 S2P_Lmt6__24: 8 SBMU
 SG_ S2P_Lmt6_Under_Utank1_24 : 0|16@1+ (0.1,0) [0|6553.5] "V"  PC
 SG_ S2P_Lmt6_Under_Utank2_24 : 16|16@1+ (0.1,0) [0|6553.5] "V"  PC
 SG_ S2P_Lmt6_Under_Utank3_24 : 32|16@1+ (0.1,0) [0|6553.5] "V"  PC
 SG_ S2P_Lmt6_Under_DUtank_24 : 48|16@1+ (0.1,0) [0|6553.5] "V"  PC

BO_ 2416897625 S2P_Lmt6__25: 8 SBMU
 SG_ S2P_Lmt6_Under_Utank1_25 : 0|16@1+ (0.1,0) [0|6553.5] "V"  PC
 SG_ S2P_Lmt6_Under_Utank2_25 : 16|16@1+ (0.1,0) [0|6553.5] "V"  PC
 SG_ S2P_Lmt6_Under_Utank3_25 : 32|16@1+ (0.1,0) [0|6553.5] "V"  PC
 SG_ S2P_Lmt6_Under_DUtank_25 : 48|16@1+ (0.1,0) [0|6553.5] "V"  PC

BO_ 2416897626 S2P_Lmt6__26: 8 SBMU
 SG_ S2P_Lmt6_Under_Utank1_26 : 0|16@1+ (0.1,0) [0|6553.5] "V"  PC
 SG_ S2P_Lmt6_Under_Utank2_26 : 16|16@1+ (0.1,0) [0|6553.5] "V"  PC
 SG_ S2P_Lmt6_Under_Utank3_26 : 32|16@1+ (0.1,0) [0|6553.5] "V"  PC
 SG_ S2P_Lmt6_Under_DUtank_26 : 48|16@1+ (0.1,0) [0|6553.5] "V"  PC

BO_ 2416897627 S2P_Lmt6__27: 8 SBMU
 SG_ S2P_Lmt6_Under_Utank1_27 : 0|16@1+ (0.1,0) [0|6553.5] "V"  PC
 SG_ S2P_Lmt6_Under_Utank2_27 : 16|16@1+ (0.1,0) [0|6553.5] "V"  PC
 SG_ S2P_Lmt6_Under_Utank3_27 : 32|16@1+ (0.1,0) [0|6553.5] "V"  PC
 SG_ S2P_Lmt6_Under_DUtank_27 : 48|16@1+ (0.1,0) [0|6553.5] "V"  PC

BO_ 2416897628 S2P_Lmt6__28: 8 SBMU
 SG_ S2P_Lmt6_Under_Utank1_28 : 0|16@1+ (0.1,0) [0|6553.5] "V"  PC
 SG_ S2P_Lmt6_Under_Utank2_28 : 16|16@1+ (0.1,0) [0|6553.5] "V"  PC
 SG_ S2P_Lmt6_Under_Utank3_28 : 32|16@1+ (0.1,0) [0|6553.5] "V"  PC
 SG_ S2P_Lmt6_Under_DUtank_28 : 48|16@1+ (0.1,0) [0|6553.5] "V"  PC

BO_ 2416897629 S2P_Lmt6__29: 8 SBMU
 SG_ S2P_Lmt6_Under_Utank1_29 : 0|16@1+ (0.1,0) [0|6553.5] "V"  PC
 SG_ S2P_Lmt6_Under_Utank2_29 : 16|16@1+ (0.1,0) [0|6553.5] "V"  PC
 SG_ S2P_Lmt6_Under_Utank3_29 : 32|16@1+ (0.1,0) [0|6553.5] "V"  PC
 SG_ S2P_Lmt6_Under_DUtank_29 : 48|16@1+ (0.1,0) [0|6553.5] "V"  PC

BO_ 2416897630 S2P_Lmt6__30: 8 SBMU
 SG_ S2P_Lmt6_Under_Utank1_30 : 0|16@1+ (0.1,0) [0|6553.5] "V"  PC
 SG_ S2P_Lmt6_Under_Utank2_30 : 16|16@1+ (0.1,0) [0|6553.5] "V"  PC
 SG_ S2P_Lmt6_Under_Utank3_30 : 32|16@1+ (0.1,0) [0|6553.5] "V"  PC
 SG_ S2P_Lmt6_Under_DUtank_30 : 48|16@1+ (0.1,0) [0|6553.5] "V"  PC

BO_ 2416897631 S2P_Lmt6__31: 8 SBMU
 SG_ S2P_Lmt6_Under_Utank1_31 : 0|16@1+ (0.1,0) [0|6553.5] "V"  PC
 SG_ S2P_Lmt6_Under_Utank2_31 : 16|16@1+ (0.1,0) [0|6553.5] "V"  PC
 SG_ S2P_Lmt6_Under_Utank3_31 : 32|16@1+ (0.1,0) [0|6553.5] "V"  PC
 SG_ S2P_Lmt6_Under_DUtank_31 : 48|16@1+ (0.1,0) [0|6553.5] "V"  PC

BO_ 2416897632 S2P_Lmt6__32: 8 SBMU
 SG_ S2P_Lmt6_Under_Utank1_32 : 0|16@1+ (0.1,0) [0|6553.5] "V"  PC
 SG_ S2P_Lmt6_Under_Utank2_32 : 16|16@1+ (0.1,0) [0|6553.5] "V"  PC
 SG_ S2P_Lmt6_Under_Utank3_32 : 32|16@1+ (0.1,0) [0|6553.5] "V"  PC
 SG_ S2P_Lmt6_Under_DUtank_32 : 48|16@1+ (0.1,0) [0|6553.5] "V"  PC

BO_ 2416897633 S2P_Lmt6__33: 8 SBMU
 SG_ S2P_Lmt6_Under_Utank1_33 : 0|16@1+ (0.1,0) [0|6553.5] "V"  PC
 SG_ S2P_Lmt6_Under_Utank2_33 : 16|16@1+ (0.1,0) [0|6553.5] "V"  PC
 SG_ S2P_Lmt6_Under_Utank3_33 : 32|16@1+ (0.1,0) [0|6553.5] "V"  PC
 SG_ S2P_Lmt6_Under_DUtank_33 : 48|16@1+ (0.1,0) [0|6553.5] "V"  PC

BO_ 2416897634 S2P_Lmt6__34: 8 SBMU
 SG_ S2P_Lmt6_Under_Utank1_34 : 0|16@1+ (0.1,0) [0|6553.5] "V"  PC
 SG_ S2P_Lmt6_Under_Utank2_34 : 16|16@1+ (0.1,0) [0|6553.5] "V"  PC
 SG_ S2P_Lmt6_Under_Utank3_34 : 32|16@1+ (0.1,0) [0|6553.5] "V"  PC
 SG_ S2P_Lmt6_Under_DUtank_34 : 48|16@1+ (0.1,0) [0|6553.5] "V"  PC

BO_ 2416897635 S2P_Lmt6__35: 8 SBMU
 SG_ S2P_Lmt6_Under_Utank1_35 : 0|16@1+ (0.1,0) [0|6553.5] "V"  PC
 SG_ S2P_Lmt6_Under_Utank2_35 : 16|16@1+ (0.1,0) [0|6553.5] "V"  PC
 SG_ S2P_Lmt6_Under_Utank3_35 : 32|16@1+ (0.1,0) [0|6553.5] "V"  PC
 SG_ S2P_Lmt6_Under_DUtank_35 : 48|16@1+ (0.1,0) [0|6553.5] "V"  PC

BO_ 2416897636 S2P_Lmt6__36: 8 SBMU
 SG_ S2P_Lmt6_Under_Utank1_36 : 0|16@1+ (0.1,0) [0|6553.5] "V"  PC
 SG_ S2P_Lmt6_Under_Utank2_36 : 16|16@1+ (0.1,0) [0|6553.5] "V"  PC
 SG_ S2P_Lmt6_Under_Utank3_36 : 32|16@1+ (0.1,0) [0|6553.5] "V"  PC
 SG_ S2P_Lmt6_Under_DUtank_36 : 48|16@1+ (0.1,0) [0|6553.5] "V"  PC

BO_ 2416897637 S2P_Lmt6__37: 8 SBMU
 SG_ S2P_Lmt6_Under_Utank1_37 : 0|16@1+ (0.1,0) [0|6553.5] "V"  PC
 SG_ S2P_Lmt6_Under_Utank2_37 : 16|16@1+ (0.1,0) [0|6553.5] "V"  PC
 SG_ S2P_Lmt6_Under_Utank3_37 : 32|16@1+ (0.1,0) [0|6553.5] "V"  PC
 SG_ S2P_Lmt6_Under_DUtank_37 : 48|16@1+ (0.1,0) [0|6553.5] "V"  PC

BO_ 2416897638 S2P_Lmt6__38: 8 SBMU
 SG_ S2P_Lmt6_Under_Utank1_38 : 0|16@1+ (0.1,0) [0|6553.5] "V"  PC
 SG_ S2P_Lmt6_Under_Utank2_38 : 16|16@1+ (0.1,0) [0|6553.5] "V"  PC
 SG_ S2P_Lmt6_Under_Utank3_38 : 32|16@1+ (0.1,0) [0|6553.5] "V"  PC
 SG_ S2P_Lmt6_Under_DUtank_38 : 48|16@1+ (0.1,0) [0|6553.5] "V"  PC

BO_ 2416897639 S2P_Lmt6__39: 8 SBMU
 SG_ S2P_Lmt6_Under_Utank1_39 : 0|16@1+ (0.1,0) [0|6553.5] "V"  PC
 SG_ S2P_Lmt6_Under_Utank2_39 : 16|16@1+ (0.1,0) [0|6553.5] "V"  PC
 SG_ S2P_Lmt6_Under_Utank3_39 : 32|16@1+ (0.1,0) [0|6553.5] "V"  PC
 SG_ S2P_Lmt6_Under_DUtank_39 : 48|16@1+ (0.1,0) [0|6553.5] "V"  PC

BO_ 2416897640 S2P_Lmt6__40: 8 SBMU
 SG_ S2P_Lmt6_Under_Utank1_40 : 0|16@1+ (0.1,0) [0|6553.5] "V"  PC
 SG_ S2P_Lmt6_Under_Utank2_40 : 16|16@1+ (0.1,0) [0|6553.5] "V"  PC
 SG_ S2P_Lmt6_Under_Utank3_40 : 32|16@1+ (0.1,0) [0|6553.5] "V"  PC
 SG_ S2P_Lmt6_Under_DUtank_40 : 48|16@1+ (0.1,0) [0|6553.5] "V"  PC

BO_ 2416897641 S2P_Lmt6__41: 8 SBMU
 SG_ S2P_Lmt6_Under_Utank1_41 : 0|16@1+ (0.1,0) [0|6553.5] "V"  PC
 SG_ S2P_Lmt6_Under_Utank2_41 : 16|16@1+ (0.1,0) [0|6553.5] "V"  PC
 SG_ S2P_Lmt6_Under_Utank3_41 : 32|16@1+ (0.1,0) [0|6553.5] "V"  PC
 SG_ S2P_Lmt6_Under_DUtank_41 : 48|16@1+ (0.1,0) [0|6553.5] "V"  PC

BO_ 2416897642 S2P_Lmt6__42: 8 SBMU
 SG_ S2P_Lmt6_Under_Utank1_42 : 0|16@1+ (0.1,0) [0|6553.5] "V"  PC
 SG_ S2P_Lmt6_Under_Utank2_42 : 16|16@1+ (0.1,0) [0|6553.5] "V"  PC
 SG_ S2P_Lmt6_Under_Utank3_42 : 32|16@1+ (0.1,0) [0|6553.5] "V"  PC
 SG_ S2P_Lmt6_Under_DUtank_42 : 48|16@1+ (0.1,0) [0|6553.5] "V"  PC

BO_ 2416897643 S2P_Lmt6__43: 8 SBMU
 SG_ S2P_Lmt6_Under_Utank1_43 : 0|16@1+ (0.1,0) [0|6553.5] "V"  PC
 SG_ S2P_Lmt6_Under_Utank2_43 : 16|16@1+ (0.1,0) [0|6553.5] "V"  PC
 SG_ S2P_Lmt6_Under_Utank3_43 : 32|16@1+ (0.1,0) [0|6553.5] "V"  PC
 SG_ S2P_Lmt6_Under_DUtank_43 : 48|16@1+ (0.1,0) [0|6553.5] "V"  PC

BO_ 2416897644 S2P_Lmt6__44: 8 SBMU
 SG_ S2P_Lmt6_Under_Utank1_44 : 0|16@1+ (0.1,0) [0|6553.5] "V"  PC
 SG_ S2P_Lmt6_Under_Utank2_44 : 16|16@1+ (0.1,0) [0|6553.5] "V"  PC
 SG_ S2P_Lmt6_Under_Utank3_44 : 32|16@1+ (0.1,0) [0|6553.5] "V"  PC
 SG_ S2P_Lmt6_Under_DUtank_44 : 48|16@1+ (0.1,0) [0|6553.5] "V"  PC

BO_ 2416897645 S2P_Lmt6__45: 8 SBMU
 SG_ S2P_Lmt6_Under_Utank1_45 : 0|16@1+ (0.1,0) [0|6553.5] "V"  PC
 SG_ S2P_Lmt6_Under_Utank2_45 : 16|16@1+ (0.1,0) [0|6553.5] "V"  PC
 SG_ S2P_Lmt6_Under_Utank3_45 : 32|16@1+ (0.1,0) [0|6553.5] "V"  PC
 SG_ S2P_Lmt6_Under_DUtank_45 : 48|16@1+ (0.1,0) [0|6553.5] "V"  PC

BO_ 2416897646 S2P_Lmt6__46: 8 SBMU
 SG_ S2P_Lmt6_Under_Utank1_46 : 0|16@1+ (0.1,0) [0|6553.5] "V"  PC
 SG_ S2P_Lmt6_Under_Utank2_46 : 16|16@1+ (0.1,0) [0|6553.5] "V"  PC
 SG_ S2P_Lmt6_Under_Utank3_46 : 32|16@1+ (0.1,0) [0|6553.5] "V"  PC
 SG_ S2P_Lmt6_Under_DUtank_46 : 48|16@1+ (0.1,0) [0|6553.5] "V"  PC

BO_ 2416897647 S2P_Lmt6__47: 8 SBMU
 SG_ S2P_Lmt6_Under_Utank1_47 : 0|16@1+ (0.1,0) [0|6553.5] "V"  PC
 SG_ S2P_Lmt6_Under_Utank2_47 : 16|16@1+ (0.1,0) [0|6553.5] "V"  PC
 SG_ S2P_Lmt6_Under_Utank3_47 : 32|16@1+ (0.1,0) [0|6553.5] "V"  PC
 SG_ S2P_Lmt6_Under_DUtank_47 : 48|16@1+ (0.1,0) [0|6553.5] "V"  PC

BO_ 2416897648 S2P_Lmt6__48: 8 SBMU
 SG_ S2P_Lmt6_Under_Utank1_48 : 0|16@1+ (0.1,0) [0|6553.5] "V"  PC
 SG_ S2P_Lmt6_Under_Utank2_48 : 16|16@1+ (0.1,0) [0|6553.5] "V"  PC
 SG_ S2P_Lmt6_Under_Utank3_48 : 32|16@1+ (0.1,0) [0|6553.5] "V"  PC
 SG_ S2P_Lmt6_Under_DUtank_48 : 48|16@1+ (0.1,0) [0|6553.5] "V"  PC

BO_ 2416897649 S2P_Lmt6__49: 8 SBMU
 SG_ S2P_Lmt6_Under_Utank1_49 : 0|16@1+ (0.1,0) [0|6553.5] "V"  PC
 SG_ S2P_Lmt6_Under_Utank2_49 : 16|16@1+ (0.1,0) [0|6553.5] "V"  PC
 SG_ S2P_Lmt6_Under_Utank3_49 : 32|16@1+ (0.1,0) [0|6553.5] "V"  PC
 SG_ S2P_Lmt6_Under_DUtank_49 : 48|16@1+ (0.1,0) [0|6553.5] "V"  PC

BO_ 2416897650 S2P_Lmt6__50: 8 SBMU
 SG_ S2P_Lmt6_Under_Utank1_50 : 0|16@1+ (0.1,0) [0|6553.5] "V"  PC
 SG_ S2P_Lmt6_Under_Utank2_50 : 16|16@1+ (0.1,0) [0|6553.5] "V"  PC
 SG_ S2P_Lmt6_Under_Utank3_50 : 32|16@1+ (0.1,0) [0|6553.5] "V"  PC
 SG_ S2P_Lmt6_Under_DUtank_50 : 48|16@1+ (0.1,0) [0|6553.5] "V"  PC

BO_ 2416897651 S2P_Lmt6__51: 8 SBMU
 SG_ S2P_Lmt6_Under_Utank1_51 : 0|16@1+ (0.1,0) [0|6553.5] "V"  PC
 SG_ S2P_Lmt6_Under_Utank2_51 : 16|16@1+ (0.1,0) [0|6553.5] "V"  PC
 SG_ S2P_Lmt6_Under_Utank3_51 : 32|16@1+ (0.1,0) [0|6553.5] "V"  PC
 SG_ S2P_Lmt6_Under_DUtank_51 : 48|16@1+ (0.1,0) [0|6553.5] "V"  PC

BO_ 2416897652 S2P_Lmt6__52: 8 SBMU
 SG_ S2P_Lmt6_Under_Utank1_52 : 0|16@1+ (0.1,0) [0|6553.5] "V"  PC
 SG_ S2P_Lmt6_Under_Utank2_52 : 16|16@1+ (0.1,0) [0|6553.5] "V"  PC
 SG_ S2P_Lmt6_Under_Utank3_52 : 32|16@1+ (0.1,0) [0|6553.5] "V"  PC
 SG_ S2P_Lmt6_Under_DUtank_52 : 48|16@1+ (0.1,0) [0|6553.5] "V"  PC

BO_ 2416897653 S2P_Lmt6__53: 8 SBMU
 SG_ S2P_Lmt6_Under_Utank1_53 : 0|16@1+ (0.1,0) [0|6553.5] "V"  PC
 SG_ S2P_Lmt6_Under_Utank2_53 : 16|16@1+ (0.1,0) [0|6553.5] "V"  PC
 SG_ S2P_Lmt6_Under_Utank3_53 : 32|16@1+ (0.1,0) [0|6553.5] "V"  PC
 SG_ S2P_Lmt6_Under_DUtank_53 : 48|16@1+ (0.1,0) [0|6553.5] "V"  PC

BO_ 2416897654 S2P_Lmt6__54: 8 SBMU
 SG_ S2P_Lmt6_Under_Utank1_54 : 0|16@1+ (0.1,0) [0|6553.5] "V"  PC
 SG_ S2P_Lmt6_Under_Utank2_54 : 16|16@1+ (0.1,0) [0|6553.5] "V"  PC
 SG_ S2P_Lmt6_Under_Utank3_54 : 32|16@1+ (0.1,0) [0|6553.5] "V"  PC
 SG_ S2P_Lmt6_Under_DUtank_54 : 48|16@1+ (0.1,0) [0|6553.5] "V"  PC

BO_ 2416897655 S2P_Lmt6__55: 8 SBMU
 SG_ S2P_Lmt6_Under_Utank1_55 : 0|16@1+ (0.1,0) [0|6553.5] "V"  PC
 SG_ S2P_Lmt6_Under_Utank2_55 : 16|16@1+ (0.1,0) [0|6553.5] "V"  PC
 SG_ S2P_Lmt6_Under_Utank3_55 : 32|16@1+ (0.1,0) [0|6553.5] "V"  PC
 SG_ S2P_Lmt6_Under_DUtank_55 : 48|16@1+ (0.1,0) [0|6553.5] "V"  PC

BO_ 2416897656 S2P_Lmt6__56: 8 SBMU
 SG_ S2P_Lmt6_Under_Utank1_56 : 0|16@1+ (0.1,0) [0|6553.5] "V"  PC
 SG_ S2P_Lmt6_Under_Utank2_56 : 16|16@1+ (0.1,0) [0|6553.5] "V"  PC
 SG_ S2P_Lmt6_Under_Utank3_56 : 32|16@1+ (0.1,0) [0|6553.5] "V"  PC
 SG_ S2P_Lmt6_Under_DUtank_56 : 48|16@1+ (0.1,0) [0|6553.5] "V"  PC

BO_ 2416897657 S2P_Lmt6__57: 8 SBMU
 SG_ S2P_Lmt6_Under_Utank1_57 : 0|16@1+ (0.1,0) [0|6553.5] "V"  PC
 SG_ S2P_Lmt6_Under_Utank2_57 : 16|16@1+ (0.1,0) [0|6553.5] "V"  PC
 SG_ S2P_Lmt6_Under_Utank3_57 : 32|16@1+ (0.1,0) [0|6553.5] "V"  PC
 SG_ S2P_Lmt6_Under_DUtank_57 : 48|16@1+ (0.1,0) [0|6553.5] "V"  PC

BO_ 2416897658 S2P_Lmt6__58: 8 SBMU
 SG_ S2P_Lmt6_Under_Utank1_58 : 0|16@1+ (0.1,0) [0|6553.5] "V"  PC
 SG_ S2P_Lmt6_Under_Utank2_58 : 16|16@1+ (0.1,0) [0|6553.5] "V"  PC
 SG_ S2P_Lmt6_Under_Utank3_58 : 32|16@1+ (0.1,0) [0|6553.5] "V"  PC
 SG_ S2P_Lmt6_Under_DUtank_58 : 48|16@1+ (0.1,0) [0|6553.5] "V"  PC

BO_ 2416897659 S2P_Lmt6__59: 8 SBMU
 SG_ S2P_Lmt6_Under_Utank1_59 : 0|16@1+ (0.1,0) [0|6553.5] "V"  PC
 SG_ S2P_Lmt6_Under_Utank2_59 : 16|16@1+ (0.1,0) [0|6553.5] "V"  PC
 SG_ S2P_Lmt6_Under_Utank3_59 : 32|16@1+ (0.1,0) [0|6553.5] "V"  PC
 SG_ S2P_Lmt6_Under_DUtank_59 : 48|16@1+ (0.1,0) [0|6553.5] "V"  PC

BO_ 2416897660 S2P_Lmt6__60: 8 SBMU
 SG_ S2P_Lmt6_Under_Utank1_60 : 0|16@1+ (0.1,0) [0|6553.5] "V"  PC
 SG_ S2P_Lmt6_Under_Utank2_60 : 16|16@1+ (0.1,0) [0|6553.5] "V"  PC
 SG_ S2P_Lmt6_Under_Utank3_60 : 32|16@1+ (0.1,0) [0|6553.5] "V"  PC
 SG_ S2P_Lmt6_Under_DUtank_60 : 48|16@1+ (0.1,0) [0|6553.5] "V"  PC

BO_ 2416897661 S2P_Lmt6__61: 8 SBMU
 SG_ S2P_Lmt6_Under_Utank1_61 : 0|16@1+ (0.1,0) [0|6553.5] "V"  PC
 SG_ S2P_Lmt6_Under_Utank2_61 : 16|16@1+ (0.1,0) [0|6553.5] "V"  PC
 SG_ S2P_Lmt6_Under_Utank3_61 : 32|16@1+ (0.1,0) [0|6553.5] "V"  PC
 SG_ S2P_Lmt6_Under_DUtank_61 : 48|16@1+ (0.1,0) [0|6553.5] "V"  PC

BO_ 2416897662 S2P_Lmt6__62: 8 SBMU
 SG_ S2P_Lmt6_Under_Utank1_62 : 0|16@1+ (0.1,0) [0|6553.5] "V"  PC
 SG_ S2P_Lmt6_Under_Utank2_62 : 16|16@1+ (0.1,0) [0|6553.5] "V"  PC
 SG_ S2P_Lmt6_Under_Utank3_62 : 32|16@1+ (0.1,0) [0|6553.5] "V"  PC
 SG_ S2P_Lmt6_Under_DUtank_62 : 48|16@1+ (0.1,0) [0|6553.5] "V"  PC

BO_ 2416897663 S2P_Lmt6__63: 8 SBMU
 SG_ S2P_Lmt6_Under_Utank1_63 : 0|16@1+ (0.1,0) [0|6553.5] "V"  PC
 SG_ S2P_Lmt6_Under_Utank2_63 : 16|16@1+ (0.1,0) [0|6553.5] "V"  PC
 SG_ S2P_Lmt6_Under_Utank3_63 : 32|16@1+ (0.1,0) [0|6553.5] "V"  PC
 SG_ S2P_Lmt6_Under_DUtank_63 : 48|16@1+ (0.1,0) [0|6553.5] "V"  PC

BO_ 2416963137 S2P_Lmt7__01: 8 SBMU
 SG_ S2P_Lmt7_Extreme_UcellMax_01 : 0|16@1+ (1,0) [0|65535] "mV"  PC
 SG_ S2P_Lmt7_Extreme_UcellMin_01 : 16|16@1+ (1,0) [0|65535] "mV"  PC
 SG_ S2P_Lmt7_Extreme_TcellMax_01 : 32|8@1+ (1,-50) [-50|205] "℃"  PC
 SG_ S2P_Lmt7_Extreme_TcellMin_01 : 40|8@1+ (1,-50) [-50|205] "℃"  PC

BO_ 2416963138 S2P_Lmt7__02: 8 SBMU
 SG_ S2P_Lmt7_Extreme_UcellMax_02 : 0|16@1+ (1,0) [0|65535] "mV"  PC
 SG_ S2P_Lmt7_Extreme_UcellMin_02 : 16|16@1+ (1,0) [0|65535] "mV"  PC
 SG_ S2P_Lmt7_Extreme_TcellMax_02 : 32|8@1+ (1,-50) [-50|205] "℃"  PC
 SG_ S2P_Lmt7_Extreme_TcellMin_02 : 40|8@1+ (1,-50) [-50|205] "℃"  PC

BO_ 2416963139 S2P_Lmt7__03: 8 SBMU
 SG_ S2P_Lmt7_Extreme_UcellMax_03 : 0|16@1+ (1,0) [0|65535] "mV"  PC
 SG_ S2P_Lmt7_Extreme_UcellMin_03 : 16|16@1+ (1,0) [0|65535] "mV"  PC
 SG_ S2P_Lmt7_Extreme_TcellMax_03 : 32|8@1+ (1,-50) [-50|205] "℃"  PC
 SG_ S2P_Lmt7_Extreme_TcellMin_03 : 40|8@1+ (1,-50) [-50|205] "℃"  PC

BO_ 2416963140 S2P_Lmt7__04: 8 SBMU
 SG_ S2P_Lmt7_Extreme_UcellMax_04 : 0|16@1+ (1,0) [0|65535] "mV"  PC
 SG_ S2P_Lmt7_Extreme_UcellMin_04 : 16|16@1+ (1,0) [0|65535] "mV"  PC
 SG_ S2P_Lmt7_Extreme_TcellMax_04 : 32|8@1+ (1,-50) [-50|205] "℃"  PC
 SG_ S2P_Lmt7_Extreme_TcellMin_04 : 40|8@1+ (1,-50) [-50|205] "℃"  PC

BO_ 2416963141 S2P_Lmt7__05: 8 SBMU
 SG_ S2P_Lmt7_Extreme_UcellMax_05 : 0|16@1+ (1,0) [0|65535] "mV"  PC
 SG_ S2P_Lmt7_Extreme_UcellMin_05 : 16|16@1+ (1,0) [0|65535] "mV"  PC
 SG_ S2P_Lmt7_Extreme_TcellMax_05 : 32|8@1+ (1,-50) [-50|205] "℃"  PC
 SG_ S2P_Lmt7_Extreme_TcellMin_05 : 40|8@1+ (1,-50) [-50|205] "℃"  PC

BO_ 2416963142 S2P_Lmt7__06: 8 SBMU
 SG_ S2P_Lmt7_Extreme_UcellMax_06 : 0|16@1+ (1,0) [0|65535] "mV"  PC
 SG_ S2P_Lmt7_Extreme_UcellMin_06 : 16|16@1+ (1,0) [0|65535] "mV"  PC
 SG_ S2P_Lmt7_Extreme_TcellMax_06 : 32|8@1+ (1,-50) [-50|205] "℃"  PC
 SG_ S2P_Lmt7_Extreme_TcellMin_06 : 40|8@1+ (1,-50) [-50|205] "℃"  PC

BO_ 2416963143 S2P_Lmt7__07: 8 SBMU
 SG_ S2P_Lmt7_Extreme_UcellMax_07 : 0|16@1+ (1,0) [0|65535] "mV"  PC
 SG_ S2P_Lmt7_Extreme_UcellMin_07 : 16|16@1+ (1,0) [0|65535] "mV"  PC
 SG_ S2P_Lmt7_Extreme_TcellMax_07 : 32|8@1+ (1,-50) [-50|205] "℃"  PC
 SG_ S2P_Lmt7_Extreme_TcellMin_07 : 40|8@1+ (1,-50) [-50|205] "℃"  PC

BO_ 2416963144 S2P_Lmt7__08: 8 SBMU
 SG_ S2P_Lmt7_Extreme_UcellMax_08 : 0|16@1+ (1,0) [0|65535] "mV"  PC
 SG_ S2P_Lmt7_Extreme_UcellMin_08 : 16|16@1+ (1,0) [0|65535] "mV"  PC
 SG_ S2P_Lmt7_Extreme_TcellMax_08 : 32|8@1+ (1,-50) [-50|205] "℃"  PC
 SG_ S2P_Lmt7_Extreme_TcellMin_08 : 40|8@1+ (1,-50) [-50|205] "℃"  PC

BO_ 2416963145 S2P_Lmt7__09: 8 SBMU
 SG_ S2P_Lmt7_Extreme_UcellMax_09 : 0|16@1+ (1,0) [0|65535] "mV"  PC
 SG_ S2P_Lmt7_Extreme_UcellMin_09 : 16|16@1+ (1,0) [0|65535] "mV"  PC
 SG_ S2P_Lmt7_Extreme_TcellMax_09 : 32|8@1+ (1,-50) [-50|205] "℃"  PC
 SG_ S2P_Lmt7_Extreme_TcellMin_09 : 40|8@1+ (1,-50) [-50|205] "℃"  PC

BO_ 2416963146 S2P_Lmt7__10: 8 SBMU
 SG_ S2P_Lmt7_Extreme_UcellMax_10 : 0|16@1+ (1,0) [0|65535] "mV"  PC
 SG_ S2P_Lmt7_Extreme_UcellMin_10 : 16|16@1+ (1,0) [0|65535] "mV"  PC
 SG_ S2P_Lmt7_Extreme_TcellMax_10 : 32|8@1+ (1,-50) [-50|205] "℃"  PC
 SG_ S2P_Lmt7_Extreme_TcellMin_10 : 40|8@1+ (1,-50) [-50|205] "℃"  PC

BO_ 2416963147 S2P_Lmt7__11: 8 SBMU
 SG_ S2P_Lmt7_Extreme_UcellMax_11 : 0|16@1+ (1,0) [0|65535] "mV"  PC
 SG_ S2P_Lmt7_Extreme_UcellMin_11 : 16|16@1+ (1,0) [0|65535] "mV"  PC
 SG_ S2P_Lmt7_Extreme_TcellMax_11 : 32|8@1+ (1,-50) [-50|205] "℃"  PC
 SG_ S2P_Lmt7_Extreme_TcellMin_11 : 40|8@1+ (1,-50) [-50|205] "℃"  PC

BO_ 2416963148 S2P_Lmt7__12: 8 SBMU
 SG_ S2P_Lmt7_Extreme_UcellMax_12 : 0|16@1+ (1,0) [0|65535] "mV"  PC
 SG_ S2P_Lmt7_Extreme_UcellMin_12 : 16|16@1+ (1,0) [0|65535] "mV"  PC
 SG_ S2P_Lmt7_Extreme_TcellMax_12 : 32|8@1+ (1,-50) [-50|205] "℃"  PC
 SG_ S2P_Lmt7_Extreme_TcellMin_12 : 40|8@1+ (1,-50) [-50|205] "℃"  PC

BO_ 2416963149 S2P_Lmt7__13: 8 SBMU
 SG_ S2P_Lmt7_Extreme_UcellMax_13 : 0|16@1+ (1,0) [0|65535] "mV"  PC
 SG_ S2P_Lmt7_Extreme_UcellMin_13 : 16|16@1+ (1,0) [0|65535] "mV"  PC
 SG_ S2P_Lmt7_Extreme_TcellMax_13 : 32|8@1+ (1,-50) [-50|205] "℃"  PC
 SG_ S2P_Lmt7_Extreme_TcellMin_13 : 40|8@1+ (1,-50) [-50|205] "℃"  PC

BO_ 2416963150 S2P_Lmt7__14: 8 SBMU
 SG_ S2P_Lmt7_Extreme_UcellMax_14 : 0|16@1+ (1,0) [0|65535] "mV"  PC
 SG_ S2P_Lmt7_Extreme_UcellMin_14 : 16|16@1+ (1,0) [0|65535] "mV"  PC
 SG_ S2P_Lmt7_Extreme_TcellMax_14 : 32|8@1+ (1,-50) [-50|205] "℃"  PC
 SG_ S2P_Lmt7_Extreme_TcellMin_14 : 40|8@1+ (1,-50) [-50|205] "℃"  PC

BO_ 2416963151 S2P_Lmt7__15: 8 SBMU
 SG_ S2P_Lmt7_Extreme_UcellMax_15 : 0|16@1+ (1,0) [0|65535] "mV"  PC
 SG_ S2P_Lmt7_Extreme_UcellMin_15 : 16|16@1+ (1,0) [0|65535] "mV"  PC
 SG_ S2P_Lmt7_Extreme_TcellMax_15 : 32|8@1+ (1,-50) [-50|205] "℃"  PC
 SG_ S2P_Lmt7_Extreme_TcellMin_15 : 40|8@1+ (1,-50) [-50|205] "℃"  PC

BO_ 2416963152 S2P_Lmt7__16: 8 SBMU
 SG_ S2P_Lmt7_Extreme_UcellMax_16 : 0|16@1+ (1,0) [0|65535] "mV"  PC
 SG_ S2P_Lmt7_Extreme_UcellMin_16 : 16|16@1+ (1,0) [0|65535] "mV"  PC
 SG_ S2P_Lmt7_Extreme_TcellMax_16 : 32|8@1+ (1,-50) [-50|205] "℃"  PC
 SG_ S2P_Lmt7_Extreme_TcellMin_16 : 40|8@1+ (1,-50) [-50|205] "℃"  PC

BO_ 2416963153 S2P_Lmt7__17: 8 SBMU
 SG_ S2P_Lmt7_Extreme_UcellMax_17 : 0|16@1+ (1,0) [0|65535] "mV"  PC
 SG_ S2P_Lmt7_Extreme_UcellMin_17 : 16|16@1+ (1,0) [0|65535] "mV"  PC
 SG_ S2P_Lmt7_Extreme_TcellMax_17 : 32|8@1+ (1,-50) [-50|205] "℃"  PC
 SG_ S2P_Lmt7_Extreme_TcellMin_17 : 40|8@1+ (1,-50) [-50|205] "℃"  PC

BO_ 2416963154 S2P_Lmt7__18: 8 SBMU
 SG_ S2P_Lmt7_Extreme_UcellMax_18 : 0|16@1+ (1,0) [0|65535] "mV"  PC
 SG_ S2P_Lmt7_Extreme_UcellMin_18 : 16|16@1+ (1,0) [0|65535] "mV"  PC
 SG_ S2P_Lmt7_Extreme_TcellMax_18 : 32|8@1+ (1,-50) [-50|205] "℃"  PC
 SG_ S2P_Lmt7_Extreme_TcellMin_18 : 40|8@1+ (1,-50) [-50|205] "℃"  PC

BO_ 2416963155 S2P_Lmt7__19: 8 SBMU
 SG_ S2P_Lmt7_Extreme_UcellMax_19 : 0|16@1+ (1,0) [0|65535] "mV"  PC
 SG_ S2P_Lmt7_Extreme_UcellMin_19 : 16|16@1+ (1,0) [0|65535] "mV"  PC
 SG_ S2P_Lmt7_Extreme_TcellMax_19 : 32|8@1+ (1,-50) [-50|205] "℃"  PC
 SG_ S2P_Lmt7_Extreme_TcellMin_19 : 40|8@1+ (1,-50) [-50|205] "℃"  PC

BO_ 2416963156 S2P_Lmt7__20: 8 SBMU
 SG_ S2P_Lmt7_Extreme_UcellMax_20 : 0|16@1+ (1,0) [0|65535] "mV"  PC
 SG_ S2P_Lmt7_Extreme_UcellMin_20 : 16|16@1+ (1,0) [0|65535] "mV"  PC
 SG_ S2P_Lmt7_Extreme_TcellMax_20 : 32|8@1+ (1,-50) [-50|205] "℃"  PC
 SG_ S2P_Lmt7_Extreme_TcellMin_20 : 40|8@1+ (1,-50) [-50|205] "℃"  PC

BO_ 2416963157 S2P_Lmt7__21: 8 SBMU
 SG_ S2P_Lmt7_Extreme_UcellMax_21 : 0|16@1+ (1,0) [0|65535] "mV"  PC
 SG_ S2P_Lmt7_Extreme_UcellMin_21 : 16|16@1+ (1,0) [0|65535] "mV"  PC
 SG_ S2P_Lmt7_Extreme_TcellMax_21 : 32|8@1+ (1,-50) [-50|205] "℃"  PC
 SG_ S2P_Lmt7_Extreme_TcellMin_21 : 40|8@1+ (1,-50) [-50|205] "℃"  PC

BO_ 2416963158 S2P_Lmt7__22: 8 SBMU
 SG_ S2P_Lmt7_Extreme_UcellMax_22 : 0|16@1+ (1,0) [0|65535] "mV"  PC
 SG_ S2P_Lmt7_Extreme_UcellMin_22 : 16|16@1+ (1,0) [0|65535] "mV"  PC
 SG_ S2P_Lmt7_Extreme_TcellMax_22 : 32|8@1+ (1,-50) [-50|205] "℃"  PC
 SG_ S2P_Lmt7_Extreme_TcellMin_22 : 40|8@1+ (1,-50) [-50|205] "℃"  PC

BO_ 2416963159 S2P_Lmt7__23: 8 SBMU
 SG_ S2P_Lmt7_Extreme_UcellMax_23 : 0|16@1+ (1,0) [0|65535] "mV"  PC
 SG_ S2P_Lmt7_Extreme_UcellMin_23 : 16|16@1+ (1,0) [0|65535] "mV"  PC
 SG_ S2P_Lmt7_Extreme_TcellMax_23 : 32|8@1+ (1,-50) [-50|205] "℃"  PC
 SG_ S2P_Lmt7_Extreme_TcellMin_23 : 40|8@1+ (1,-50) [-50|205] "℃"  PC

BO_ 2416963160 S2P_Lmt7__24: 8 SBMU
 SG_ S2P_Lmt7_Extreme_UcellMax_24 : 0|16@1+ (1,0) [0|65535] "mV"  PC
 SG_ S2P_Lmt7_Extreme_UcellMin_24 : 16|16@1+ (1,0) [0|65535] "mV"  PC
 SG_ S2P_Lmt7_Extreme_TcellMax_24 : 32|8@1+ (1,-50) [-50|205] "℃"  PC
 SG_ S2P_Lmt7_Extreme_TcellMin_24 : 40|8@1+ (1,-50) [-50|205] "℃"  PC

BO_ 2416963161 S2P_Lmt7__25: 8 SBMU
 SG_ S2P_Lmt7_Extreme_UcellMax_25 : 0|16@1+ (1,0) [0|65535] "mV"  PC
 SG_ S2P_Lmt7_Extreme_UcellMin_25 : 16|16@1+ (1,0) [0|65535] "mV"  PC
 SG_ S2P_Lmt7_Extreme_TcellMax_25 : 32|8@1+ (1,-50) [-50|205] "℃"  PC
 SG_ S2P_Lmt7_Extreme_TcellMin_25 : 40|8@1+ (1,-50) [-50|205] "℃"  PC

BO_ 2416963162 S2P_Lmt7__26: 8 SBMU
 SG_ S2P_Lmt7_Extreme_UcellMax_26 : 0|16@1+ (1,0) [0|65535] "mV"  PC
 SG_ S2P_Lmt7_Extreme_UcellMin_26 : 16|16@1+ (1,0) [0|65535] "mV"  PC
 SG_ S2P_Lmt7_Extreme_TcellMax_26 : 32|8@1+ (1,-50) [-50|205] "℃"  PC
 SG_ S2P_Lmt7_Extreme_TcellMin_26 : 40|8@1+ (1,-50) [-50|205] "℃"  PC

BO_ 2416963163 S2P_Lmt7__27: 8 SBMU
 SG_ S2P_Lmt7_Extreme_UcellMax_27 : 0|16@1+ (1,0) [0|65535] "mV"  PC
 SG_ S2P_Lmt7_Extreme_UcellMin_27 : 16|16@1+ (1,0) [0|65535] "mV"  PC
 SG_ S2P_Lmt7_Extreme_TcellMax_27 : 32|8@1+ (1,-50) [-50|205] "℃"  PC
 SG_ S2P_Lmt7_Extreme_TcellMin_27 : 40|8@1+ (1,-50) [-50|205] "℃"  PC

BO_ 2416963164 S2P_Lmt7__28: 8 SBMU
 SG_ S2P_Lmt7_Extreme_UcellMax_28 : 0|16@1+ (1,0) [0|65535] "mV"  PC
 SG_ S2P_Lmt7_Extreme_UcellMin_28 : 16|16@1+ (1,0) [0|65535] "mV"  PC
 SG_ S2P_Lmt7_Extreme_TcellMax_28 : 32|8@1+ (1,-50) [-50|205] "℃"  PC
 SG_ S2P_Lmt7_Extreme_TcellMin_28 : 40|8@1+ (1,-50) [-50|205] "℃"  PC

BO_ 2416963165 S2P_Lmt7__29: 8 SBMU
 SG_ S2P_Lmt7_Extreme_UcellMax_29 : 0|16@1+ (1,0) [0|65535] "mV"  PC
 SG_ S2P_Lmt7_Extreme_UcellMin_29 : 16|16@1+ (1,0) [0|65535] "mV"  PC
 SG_ S2P_Lmt7_Extreme_TcellMax_29 : 32|8@1+ (1,-50) [-50|205] "℃"  PC
 SG_ S2P_Lmt7_Extreme_TcellMin_29 : 40|8@1+ (1,-50) [-50|205] "℃"  PC

BO_ 2416963166 S2P_Lmt7__30: 8 SBMU
 SG_ S2P_Lmt7_Extreme_UcellMax_30 : 0|16@1+ (1,0) [0|65535] "mV"  PC
 SG_ S2P_Lmt7_Extreme_UcellMin_30 : 16|16@1+ (1,0) [0|65535] "mV"  PC
 SG_ S2P_Lmt7_Extreme_TcellMax_30 : 32|8@1+ (1,-50) [-50|205] "℃"  PC
 SG_ S2P_Lmt7_Extreme_TcellMin_30 : 40|8@1+ (1,-50) [-50|205] "℃"  PC

BO_ 2416963167 S2P_Lmt7__31: 8 SBMU
 SG_ S2P_Lmt7_Extreme_UcellMax_31 : 0|16@1+ (1,0) [0|65535] "mV"  PC
 SG_ S2P_Lmt7_Extreme_UcellMin_31 : 16|16@1+ (1,0) [0|65535] "mV"  PC
 SG_ S2P_Lmt7_Extreme_TcellMax_31 : 32|8@1+ (1,-50) [-50|205] "℃"  PC
 SG_ S2P_Lmt7_Extreme_TcellMin_31 : 40|8@1+ (1,-50) [-50|205] "℃"  PC

BO_ 2416963168 S2P_Lmt7__32: 8 SBMU
 SG_ S2P_Lmt7_Extreme_UcellMax_32 : 0|16@1+ (1,0) [0|65535] "mV"  PC
 SG_ S2P_Lmt7_Extreme_UcellMin_32 : 16|16@1+ (1,0) [0|65535] "mV"  PC
 SG_ S2P_Lmt7_Extreme_TcellMax_32 : 32|8@1+ (1,-50) [-50|205] "℃"  PC
 SG_ S2P_Lmt7_Extreme_TcellMin_32 : 40|8@1+ (1,-50) [-50|205] "℃"  PC

BO_ 2416963169 S2P_Lmt7__33: 8 SBMU
 SG_ S2P_Lmt7_Extreme_UcellMax_33 : 0|16@1+ (1,0) [0|65535] "mV"  PC
 SG_ S2P_Lmt7_Extreme_UcellMin_33 : 16|16@1+ (1,0) [0|65535] "mV"  PC
 SG_ S2P_Lmt7_Extreme_TcellMax_33 : 32|8@1+ (1,-50) [-50|205] "℃"  PC
 SG_ S2P_Lmt7_Extreme_TcellMin_33 : 40|8@1+ (1,-50) [-50|205] "℃"  PC

BO_ 2416963170 S2P_Lmt7__34: 8 SBMU
 SG_ S2P_Lmt7_Extreme_UcellMax_34 : 0|16@1+ (1,0) [0|65535] "mV"  PC
 SG_ S2P_Lmt7_Extreme_UcellMin_34 : 16|16@1+ (1,0) [0|65535] "mV"  PC
 SG_ S2P_Lmt7_Extreme_TcellMax_34 : 32|8@1+ (1,-50) [-50|205] "℃"  PC
 SG_ S2P_Lmt7_Extreme_TcellMin_34 : 40|8@1+ (1,-50) [-50|205] "℃"  PC

BO_ 2416963171 S2P_Lmt7__35: 8 SBMU
 SG_ S2P_Lmt7_Extreme_UcellMax_35 : 0|16@1+ (1,0) [0|65535] "mV"  PC
 SG_ S2P_Lmt7_Extreme_UcellMin_35 : 16|16@1+ (1,0) [0|65535] "mV"  PC
 SG_ S2P_Lmt7_Extreme_TcellMax_35 : 32|8@1+ (1,-50) [-50|205] "℃"  PC
 SG_ S2P_Lmt7_Extreme_TcellMin_35 : 40|8@1+ (1,-50) [-50|205] "℃"  PC

BO_ 2416963172 S2P_Lmt7__36: 8 SBMU
 SG_ S2P_Lmt7_Extreme_UcellMax_36 : 0|16@1+ (1,0) [0|65535] "mV"  PC
 SG_ S2P_Lmt7_Extreme_UcellMin_36 : 16|16@1+ (1,0) [0|65535] "mV"  PC
 SG_ S2P_Lmt7_Extreme_TcellMax_36 : 32|8@1+ (1,-50) [-50|205] "℃"  PC
 SG_ S2P_Lmt7_Extreme_TcellMin_36 : 40|8@1+ (1,-50) [-50|205] "℃"  PC

BO_ 2416963173 S2P_Lmt7__37: 8 SBMU
 SG_ S2P_Lmt7_Extreme_UcellMax_37 : 0|16@1+ (1,0) [0|65535] "mV"  PC
 SG_ S2P_Lmt7_Extreme_UcellMin_37 : 16|16@1+ (1,0) [0|65535] "mV"  PC
 SG_ S2P_Lmt7_Extreme_TcellMax_37 : 32|8@1+ (1,-50) [-50|205] "℃"  PC
 SG_ S2P_Lmt7_Extreme_TcellMin_37 : 40|8@1+ (1,-50) [-50|205] "℃"  PC

BO_ 2416963174 S2P_Lmt7__38: 8 SBMU
 SG_ S2P_Lmt7_Extreme_UcellMax_38 : 0|16@1+ (1,0) [0|65535] "mV"  PC
 SG_ S2P_Lmt7_Extreme_UcellMin_38 : 16|16@1+ (1,0) [0|65535] "mV"  PC
 SG_ S2P_Lmt7_Extreme_TcellMax_38 : 32|8@1+ (1,-50) [-50|205] "℃"  PC
 SG_ S2P_Lmt7_Extreme_TcellMin_38 : 40|8@1+ (1,-50) [-50|205] "℃"  PC

BO_ 2416963175 S2P_Lmt7__39: 8 SBMU
 SG_ S2P_Lmt7_Extreme_UcellMax_39 : 0|16@1+ (1,0) [0|65535] "mV"  PC
 SG_ S2P_Lmt7_Extreme_UcellMin_39 : 16|16@1+ (1,0) [0|65535] "mV"  PC
 SG_ S2P_Lmt7_Extreme_TcellMax_39 : 32|8@1+ (1,-50) [-50|205] "℃"  PC
 SG_ S2P_Lmt7_Extreme_TcellMin_39 : 40|8@1+ (1,-50) [-50|205] "℃"  PC

BO_ 2416963176 S2P_Lmt7__40: 8 SBMU
 SG_ S2P_Lmt7_Extreme_UcellMax_40 : 0|16@1+ (1,0) [0|65535] "mV"  PC
 SG_ S2P_Lmt7_Extreme_UcellMin_40 : 16|16@1+ (1,0) [0|65535] "mV"  PC
 SG_ S2P_Lmt7_Extreme_TcellMax_40 : 32|8@1+ (1,-50) [-50|205] "℃"  PC
 SG_ S2P_Lmt7_Extreme_TcellMin_40 : 40|8@1+ (1,-50) [-50|205] "℃"  PC

BO_ 2416963177 S2P_Lmt7__41: 8 SBMU
 SG_ S2P_Lmt7_Extreme_UcellMax_41 : 0|16@1+ (1,0) [0|65535] "mV"  PC
 SG_ S2P_Lmt7_Extreme_UcellMin_41 : 16|16@1+ (1,0) [0|65535] "mV"  PC
 SG_ S2P_Lmt7_Extreme_TcellMax_41 : 32|8@1+ (1,-50) [-50|205] "℃"  PC
 SG_ S2P_Lmt7_Extreme_TcellMin_41 : 40|8@1+ (1,-50) [-50|205] "℃"  PC

BO_ 2416963178 S2P_Lmt7__42: 8 SBMU
 SG_ S2P_Lmt7_Extreme_UcellMax_42 : 0|16@1+ (1,0) [0|65535] "mV"  PC
 SG_ S2P_Lmt7_Extreme_UcellMin_42 : 16|16@1+ (1,0) [0|65535] "mV"  PC
 SG_ S2P_Lmt7_Extreme_TcellMax_42 : 32|8@1+ (1,-50) [-50|205] "℃"  PC
 SG_ S2P_Lmt7_Extreme_TcellMin_42 : 40|8@1+ (1,-50) [-50|205] "℃"  PC

BO_ 2416963179 S2P_Lmt7__43: 8 SBMU
 SG_ S2P_Lmt7_Extreme_UcellMax_43 : 0|16@1+ (1,0) [0|65535] "mV"  PC
 SG_ S2P_Lmt7_Extreme_UcellMin_43 : 16|16@1+ (1,0) [0|65535] "mV"  PC
 SG_ S2P_Lmt7_Extreme_TcellMax_43 : 32|8@1+ (1,-50) [-50|205] "℃"  PC
 SG_ S2P_Lmt7_Extreme_TcellMin_43 : 40|8@1+ (1,-50) [-50|205] "℃"  PC

BO_ 2416963180 S2P_Lmt7__44: 8 SBMU
 SG_ S2P_Lmt7_Extreme_UcellMax_44 : 0|16@1+ (1,0) [0|65535] "mV"  PC
 SG_ S2P_Lmt7_Extreme_UcellMin_44 : 16|16@1+ (1,0) [0|65535] "mV"  PC
 SG_ S2P_Lmt7_Extreme_TcellMax_44 : 32|8@1+ (1,-50) [-50|205] "℃"  PC
 SG_ S2P_Lmt7_Extreme_TcellMin_44 : 40|8@1+ (1,-50) [-50|205] "℃"  PC

BO_ 2416963181 S2P_Lmt7__45: 8 SBMU
 SG_ S2P_Lmt7_Extreme_UcellMax_45 : 0|16@1+ (1,0) [0|65535] "mV"  PC
 SG_ S2P_Lmt7_Extreme_UcellMin_45 : 16|16@1+ (1,0) [0|65535] "mV"  PC
 SG_ S2P_Lmt7_Extreme_TcellMax_45 : 32|8@1+ (1,-50) [-50|205] "℃"  PC
 SG_ S2P_Lmt7_Extreme_TcellMin_45 : 40|8@1+ (1,-50) [-50|205] "℃"  PC

BO_ 2416963182 S2P_Lmt7__46: 8 SBMU
 SG_ S2P_Lmt7_Extreme_UcellMax_46 : 0|16@1+ (1,0) [0|65535] "mV"  PC
 SG_ S2P_Lmt7_Extreme_UcellMin_46 : 16|16@1+ (1,0) [0|65535] "mV"  PC
 SG_ S2P_Lmt7_Extreme_TcellMax_46 : 32|8@1+ (1,-50) [-50|205] "℃"  PC
 SG_ S2P_Lmt7_Extreme_TcellMin_46 : 40|8@1+ (1,-50) [-50|205] "℃"  PC

BO_ 2416963183 S2P_Lmt7__47: 8 SBMU
 SG_ S2P_Lmt7_Extreme_UcellMax_47 : 0|16@1+ (1,0) [0|65535] "mV"  PC
 SG_ S2P_Lmt7_Extreme_UcellMin_47 : 16|16@1+ (1,0) [0|65535] "mV"  PC
 SG_ S2P_Lmt7_Extreme_TcellMax_47 : 32|8@1+ (1,-50) [-50|205] "℃"  PC
 SG_ S2P_Lmt7_Extreme_TcellMin_47 : 40|8@1+ (1,-50) [-50|205] "℃"  PC

BO_ 2416963184 S2P_Lmt7__48: 8 SBMU
 SG_ S2P_Lmt7_Extreme_UcellMax_48 : 0|16@1+ (1,0) [0|65535] "mV"  PC
 SG_ S2P_Lmt7_Extreme_UcellMin_48 : 16|16@1+ (1,0) [0|65535] "mV"  PC
 SG_ S2P_Lmt7_Extreme_TcellMax_48 : 32|8@1+ (1,-50) [-50|205] "℃"  PC
 SG_ S2P_Lmt7_Extreme_TcellMin_48 : 40|8@1+ (1,-50) [-50|205] "℃"  PC

BO_ 2416963185 S2P_Lmt7__49: 8 SBMU
 SG_ S2P_Lmt7_Extreme_UcellMax_49 : 0|16@1+ (1,0) [0|65535] "mV"  PC
 SG_ S2P_Lmt7_Extreme_UcellMin_49 : 16|16@1+ (1,0) [0|65535] "mV"  PC
 SG_ S2P_Lmt7_Extreme_TcellMax_49 : 32|8@1+ (1,-50) [-50|205] "℃"  PC
 SG_ S2P_Lmt7_Extreme_TcellMin_49 : 40|8@1+ (1,-50) [-50|205] "℃"  PC

BO_ 2416963186 S2P_Lmt7__50: 8 SBMU
 SG_ S2P_Lmt7_Extreme_UcellMax_50 : 0|16@1+ (1,0) [0|65535] "mV"  PC
 SG_ S2P_Lmt7_Extreme_UcellMin_50 : 16|16@1+ (1,0) [0|65535] "mV"  PC
 SG_ S2P_Lmt7_Extreme_TcellMax_50 : 32|8@1+ (1,-50) [-50|205] "℃"  PC
 SG_ S2P_Lmt7_Extreme_TcellMin_50 : 40|8@1+ (1,-50) [-50|205] "℃"  PC

BO_ 2416963187 S2P_Lmt7__51: 8 SBMU
 SG_ S2P_Lmt7_Extreme_UcellMax_51 : 0|16@1+ (1,0) [0|65535] "mV"  PC
 SG_ S2P_Lmt7_Extreme_UcellMin_51 : 16|16@1+ (1,0) [0|65535] "mV"  PC
 SG_ S2P_Lmt7_Extreme_TcellMax_51 : 32|8@1+ (1,-50) [-50|205] "℃"  PC
 SG_ S2P_Lmt7_Extreme_TcellMin_51 : 40|8@1+ (1,-50) [-50|205] "℃"  PC

BO_ 2416963188 S2P_Lmt7__52: 8 SBMU
 SG_ S2P_Lmt7_Extreme_UcellMax_52 : 0|16@1+ (1,0) [0|65535] "mV"  PC
 SG_ S2P_Lmt7_Extreme_UcellMin_52 : 16|16@1+ (1,0) [0|65535] "mV"  PC
 SG_ S2P_Lmt7_Extreme_TcellMax_52 : 32|8@1+ (1,-50) [-50|205] "℃"  PC
 SG_ S2P_Lmt7_Extreme_TcellMin_52 : 40|8@1+ (1,-50) [-50|205] "℃"  PC

BO_ 2416963189 S2P_Lmt7__53: 8 SBMU
 SG_ S2P_Lmt7_Extreme_UcellMax_53 : 0|16@1+ (1,0) [0|65535] "mV"  PC
 SG_ S2P_Lmt7_Extreme_UcellMin_53 : 16|16@1+ (1,0) [0|65535] "mV"  PC
 SG_ S2P_Lmt7_Extreme_TcellMax_53 : 32|8@1+ (1,-50) [-50|205] "℃"  PC
 SG_ S2P_Lmt7_Extreme_TcellMin_53 : 40|8@1+ (1,-50) [-50|205] "℃"  PC

BO_ 2416963190 S2P_Lmt7__54: 8 SBMU
 SG_ S2P_Lmt7_Extreme_UcellMax_54 : 0|16@1+ (1,0) [0|65535] "mV"  PC
 SG_ S2P_Lmt7_Extreme_UcellMin_54 : 16|16@1+ (1,0) [0|65535] "mV"  PC
 SG_ S2P_Lmt7_Extreme_TcellMax_54 : 32|8@1+ (1,-50) [-50|205] "℃"  PC
 SG_ S2P_Lmt7_Extreme_TcellMin_54 : 40|8@1+ (1,-50) [-50|205] "℃"  PC

BO_ 2416963191 S2P_Lmt7__55: 8 SBMU
 SG_ S2P_Lmt7_Extreme_UcellMax_55 : 0|16@1+ (1,0) [0|65535] "mV"  PC
 SG_ S2P_Lmt7_Extreme_UcellMin_55 : 16|16@1+ (1,0) [0|65535] "mV"  PC
 SG_ S2P_Lmt7_Extreme_TcellMax_55 : 32|8@1+ (1,-50) [-50|205] "℃"  PC
 SG_ S2P_Lmt7_Extreme_TcellMin_55 : 40|8@1+ (1,-50) [-50|205] "℃"  PC

BO_ 2416963192 S2P_Lmt7__56: 8 SBMU
 SG_ S2P_Lmt7_Extreme_UcellMax_56 : 0|16@1+ (1,0) [0|65535] "mV"  PC
 SG_ S2P_Lmt7_Extreme_UcellMin_56 : 16|16@1+ (1,0) [0|65535] "mV"  PC
 SG_ S2P_Lmt7_Extreme_TcellMax_56 : 32|8@1+ (1,-50) [-50|205] "℃"  PC
 SG_ S2P_Lmt7_Extreme_TcellMin_56 : 40|8@1+ (1,-50) [-50|205] "℃"  PC

BO_ 2416963193 S2P_Lmt7__57: 8 SBMU
 SG_ S2P_Lmt7_Extreme_UcellMax_57 : 0|16@1+ (1,0) [0|65535] "mV"  PC
 SG_ S2P_Lmt7_Extreme_UcellMin_57 : 16|16@1+ (1,0) [0|65535] "mV"  PC
 SG_ S2P_Lmt7_Extreme_TcellMax_57 : 32|8@1+ (1,-50) [-50|205] "℃"  PC
 SG_ S2P_Lmt7_Extreme_TcellMin_57 : 40|8@1+ (1,-50) [-50|205] "℃"  PC

BO_ 2416963194 S2P_Lmt7__58: 8 SBMU
 SG_ S2P_Lmt7_Extreme_UcellMax_58 : 0|16@1+ (1,0) [0|65535] "mV"  PC
 SG_ S2P_Lmt7_Extreme_UcellMin_58 : 16|16@1+ (1,0) [0|65535] "mV"  PC
 SG_ S2P_Lmt7_Extreme_TcellMax_58 : 32|8@1+ (1,-50) [-50|205] "℃"  PC
 SG_ S2P_Lmt7_Extreme_TcellMin_58 : 40|8@1+ (1,-50) [-50|205] "℃"  PC

BO_ 2416963195 S2P_Lmt7__59: 8 SBMU
 SG_ S2P_Lmt7_Extreme_UcellMax_59 : 0|16@1+ (1,0) [0|65535] "mV"  PC
 SG_ S2P_Lmt7_Extreme_UcellMin_59 : 16|16@1+ (1,0) [0|65535] "mV"  PC
 SG_ S2P_Lmt7_Extreme_TcellMax_59 : 32|8@1+ (1,-50) [-50|205] "℃"  PC
 SG_ S2P_Lmt7_Extreme_TcellMin_59 : 40|8@1+ (1,-50) [-50|205] "℃"  PC

BO_ 2416963196 S2P_Lmt7__60: 8 SBMU
 SG_ S2P_Lmt7_Extreme_UcellMax_60 : 0|16@1+ (1,0) [0|65535] "mV"  PC
 SG_ S2P_Lmt7_Extreme_UcellMin_60 : 16|16@1+ (1,0) [0|65535] "mV"  PC
 SG_ S2P_Lmt7_Extreme_TcellMax_60 : 32|8@1+ (1,-50) [-50|205] "℃"  PC
 SG_ S2P_Lmt7_Extreme_TcellMin_60 : 40|8@1+ (1,-50) [-50|205] "℃"  PC

BO_ 2416963197 S2P_Lmt7__61: 8 SBMU
 SG_ S2P_Lmt7_Extreme_UcellMax_61 : 0|16@1+ (1,0) [0|65535] "mV"  PC
 SG_ S2P_Lmt7_Extreme_UcellMin_61 : 16|16@1+ (1,0) [0|65535] "mV"  PC
 SG_ S2P_Lmt7_Extreme_TcellMax_61 : 32|8@1+ (1,-50) [-50|205] "℃"  PC
 SG_ S2P_Lmt7_Extreme_TcellMin_61 : 40|8@1+ (1,-50) [-50|205] "℃"  PC

BO_ 2416963198 S2P_Lmt7__62: 8 SBMU
 SG_ S2P_Lmt7_Extreme_UcellMax_62 : 0|16@1+ (1,0) [0|65535] "mV"  PC
 SG_ S2P_Lmt7_Extreme_UcellMin_62 : 16|16@1+ (1,0) [0|65535] "mV"  PC
 SG_ S2P_Lmt7_Extreme_TcellMax_62 : 32|8@1+ (1,-50) [-50|205] "℃"  PC
 SG_ S2P_Lmt7_Extreme_TcellMin_62 : 40|8@1+ (1,-50) [-50|205] "℃"  PC

BO_ 2416963199 S2P_Lmt7__63: 8 SBMU
 SG_ S2P_Lmt7_Extreme_UcellMax_63 : 0|16@1+ (1,0) [0|65535] "mV"  PC
 SG_ S2P_Lmt7_Extreme_UcellMin_63 : 16|16@1+ (1,0) [0|65535] "mV"  PC
 SG_ S2P_Lmt7_Extreme_TcellMax_63 : 32|8@1+ (1,-50) [-50|205] "℃"  PC
 SG_ S2P_Lmt7_Extreme_TcellMin_63 : 40|8@1+ (1,-50) [-50|205] "℃"  PC

BO_ 2417028673 S2P_Lmt8__01: 8 SBMU
 SG_ S2P_Lmt8_OverCLongThanN1_Time_01 : 0|16@1+ (1,0) [0|65535] "S"  PC
 SG_ S2P_Lmt8_OverCLongThanN2_Time_01 : 16|16@1+ (1,0) [0|65535] "S"  PC
 SG_ S2P_Lmt8_OverCLongThanN3_Time_01 : 32|16@1+ (1,0) [0|65535] "S"  PC

BO_ 2417028674 S2P_Lmt8__02: 8 SBMU
 SG_ S2P_Lmt8_OverCLongThanN1_Time_02 : 0|16@1+ (1,0) [0|65535] "S"  PC
 SG_ S2P_Lmt8_OverCLongThanN2_Time_02 : 16|16@1+ (1,0) [0|65535] "S"  PC
 SG_ S2P_Lmt8_OverCLongThanN3_Time_02 : 32|16@1+ (1,0) [0|65535] "S"  PC

BO_ 2417028675 S2P_Lmt8__03: 8 SBMU
 SG_ S2P_Lmt8_OverCLongThanN1_Time_03 : 0|16@1+ (1,0) [0|65535] "S"  PC
 SG_ S2P_Lmt8_OverCLongThanN2_Time_03 : 16|16@1+ (1,0) [0|65535] "S"  PC
 SG_ S2P_Lmt8_OverCLongThanN3_Time_03 : 32|16@1+ (1,0) [0|65535] "S"  PC

BO_ 2417028676 S2P_Lmt8__04: 8 SBMU
 SG_ S2P_Lmt8_OverCLongThanN1_Time_04 : 0|16@1+ (1,0) [0|65535] "S"  PC
 SG_ S2P_Lmt8_OverCLongThanN2_Time_04 : 16|16@1+ (1,0) [0|65535] "S"  PC
 SG_ S2P_Lmt8_OverCLongThanN3_Time_04 : 32|16@1+ (1,0) [0|65535] "S"  PC

BO_ 2417028677 S2P_Lmt8__05: 8 SBMU
 SG_ S2P_Lmt8_OverCLongThanN1_Time_05 : 0|16@1+ (1,0) [0|65535] "S"  PC
 SG_ S2P_Lmt8_OverCLongThanN2_Time_05 : 16|16@1+ (1,0) [0|65535] "S"  PC
 SG_ S2P_Lmt8_OverCLongThanN3_Time_05 : 32|16@1+ (1,0) [0|65535] "S"  PC

BO_ 2417028678 S2P_Lmt8__06: 8 SBMU
 SG_ S2P_Lmt8_OverCLongThanN1_Time_06 : 0|16@1+ (1,0) [0|65535] "S"  PC
 SG_ S2P_Lmt8_OverCLongThanN2_Time_06 : 16|16@1+ (1,0) [0|65535] "S"  PC
 SG_ S2P_Lmt8_OverCLongThanN3_Time_06 : 32|16@1+ (1,0) [0|65535] "S"  PC

BO_ 2417028679 S2P_Lmt8__07: 8 SBMU
 SG_ S2P_Lmt8_OverCLongThanN1_Time_07 : 0|16@1+ (1,0) [0|65535] "S"  PC
 SG_ S2P_Lmt8_OverCLongThanN2_Time_07 : 16|16@1+ (1,0) [0|65535] "S"  PC
 SG_ S2P_Lmt8_OverCLongThanN3_Time_07 : 32|16@1+ (1,0) [0|65535] "S"  PC

BO_ 2417028680 S2P_Lmt8__08: 8 SBMU
 SG_ S2P_Lmt8_OverCLongThanN1_Time_08 : 0|16@1+ (1,0) [0|65535] "S"  PC
 SG_ S2P_Lmt8_OverCLongThanN2_Time_08 : 16|16@1+ (1,0) [0|65535] "S"  PC
 SG_ S2P_Lmt8_OverCLongThanN3_Time_08 : 32|16@1+ (1,0) [0|65535] "S"  PC

BO_ 2417028681 S2P_Lmt8__09: 8 SBMU
 SG_ S2P_Lmt8_OverCLongThanN1_Time_09 : 0|16@1+ (1,0) [0|65535] "S"  PC
 SG_ S2P_Lmt8_OverCLongThanN2_Time_09 : 16|16@1+ (1,0) [0|65535] "S"  PC
 SG_ S2P_Lmt8_OverCLongThanN3_Time_09 : 32|16@1+ (1,0) [0|65535] "S"  PC

BO_ 2417028682 S2P_Lmt8__10: 8 SBMU
 SG_ S2P_Lmt8_OverCLongThanN1_Time_10 : 0|16@1+ (1,0) [0|65535] "S"  PC
 SG_ S2P_Lmt8_OverCLongThanN2_Time_10 : 16|16@1+ (1,0) [0|65535] "S"  PC
 SG_ S2P_Lmt8_OverCLongThanN3_Time_10 : 32|16@1+ (1,0) [0|65535] "S"  PC

BO_ 2417028683 S2P_Lmt8__11: 8 SBMU
 SG_ S2P_Lmt8_OverCLongThanN1_Time_11 : 0|16@1+ (1,0) [0|65535] "S"  PC
 SG_ S2P_Lmt8_OverCLongThanN2_Time_11 : 16|16@1+ (1,0) [0|65535] "S"  PC
 SG_ S2P_Lmt8_OverCLongThanN3_Time_11 : 32|16@1+ (1,0) [0|65535] "S"  PC

BO_ 2417028684 S2P_Lmt8__12: 8 SBMU
 SG_ S2P_Lmt8_OverCLongThanN1_Time_12 : 0|16@1+ (1,0) [0|65535] "S"  PC
 SG_ S2P_Lmt8_OverCLongThanN2_Time_12 : 16|16@1+ (1,0) [0|65535] "S"  PC
 SG_ S2P_Lmt8_OverCLongThanN3_Time_12 : 32|16@1+ (1,0) [0|65535] "S"  PC

BO_ 2417028685 S2P_Lmt8__13: 8 SBMU
 SG_ S2P_Lmt8_OverCLongThanN1_Time_13 : 0|16@1+ (1,0) [0|65535] "S"  PC
 SG_ S2P_Lmt8_OverCLongThanN2_Time_13 : 16|16@1+ (1,0) [0|65535] "S"  PC
 SG_ S2P_Lmt8_OverCLongThanN3_Time_13 : 32|16@1+ (1,0) [0|65535] "S"  PC

BO_ 2417028686 S2P_Lmt8__14: 8 SBMU
 SG_ S2P_Lmt8_OverCLongThanN1_Time_14 : 0|16@1+ (1,0) [0|65535] "S"  PC
 SG_ S2P_Lmt8_OverCLongThanN2_Time_14 : 16|16@1+ (1,0) [0|65535] "S"  PC
 SG_ S2P_Lmt8_OverCLongThanN3_Time_14 : 32|16@1+ (1,0) [0|65535] "S"  PC

BO_ 2417028687 S2P_Lmt8__15: 8 SBMU
 SG_ S2P_Lmt8_OverCLongThanN1_Time_15 : 0|16@1+ (1,0) [0|65535] "S"  PC
 SG_ S2P_Lmt8_OverCLongThanN2_Time_15 : 16|16@1+ (1,0) [0|65535] "S"  PC
 SG_ S2P_Lmt8_OverCLongThanN3_Time_15 : 32|16@1+ (1,0) [0|65535] "S"  PC

BO_ 2417028688 S2P_Lmt8__16: 8 SBMU
 SG_ S2P_Lmt8_OverCLongThanN1_Time_16 : 0|16@1+ (1,0) [0|65535] "S"  PC
 SG_ S2P_Lmt8_OverCLongThanN2_Time_16 : 16|16@1+ (1,0) [0|65535] "S"  PC
 SG_ S2P_Lmt8_OverCLongThanN3_Time_16 : 32|16@1+ (1,0) [0|65535] "S"  PC

BO_ 2417028689 S2P_Lmt8__17: 8 SBMU
 SG_ S2P_Lmt8_OverCLongThanN1_Time_17 : 0|16@1+ (1,0) [0|65535] "S"  PC
 SG_ S2P_Lmt8_OverCLongThanN2_Time_17 : 16|16@1+ (1,0) [0|65535] "S"  PC
 SG_ S2P_Lmt8_OverCLongThanN3_Time_17 : 32|16@1+ (1,0) [0|65535] "S"  PC

BO_ 2417028690 S2P_Lmt8__18: 8 SBMU
 SG_ S2P_Lmt8_OverCLongThanN1_Time_18 : 0|16@1+ (1,0) [0|65535] "S"  PC
 SG_ S2P_Lmt8_OverCLongThanN2_Time_18 : 16|16@1+ (1,0) [0|65535] "S"  PC
 SG_ S2P_Lmt8_OverCLongThanN3_Time_18 : 32|16@1+ (1,0) [0|65535] "S"  PC

BO_ 2417028691 S2P_Lmt8__19: 8 SBMU
 SG_ S2P_Lmt8_OverCLongThanN1_Time_19 : 0|16@1+ (1,0) [0|65535] "S"  PC
 SG_ S2P_Lmt8_OverCLongThanN2_Time_19 : 16|16@1+ (1,0) [0|65535] "S"  PC
 SG_ S2P_Lmt8_OverCLongThanN3_Time_19 : 32|16@1+ (1,0) [0|65535] "S"  PC

BO_ 2417028692 S2P_Lmt8__20: 8 SBMU
 SG_ S2P_Lmt8_OverCLongThanN1_Time_20 : 0|16@1+ (1,0) [0|65535] "S"  PC
 SG_ S2P_Lmt8_OverCLongThanN2_Time_20 : 16|16@1+ (1,0) [0|65535] "S"  PC
 SG_ S2P_Lmt8_OverCLongThanN3_Time_20 : 32|16@1+ (1,0) [0|65535] "S"  PC

BO_ 2417028693 S2P_Lmt8__21: 8 SBMU
 SG_ S2P_Lmt8_OverCLongThanN1_Time_21 : 0|16@1+ (1,0) [0|65535] "S"  PC
 SG_ S2P_Lmt8_OverCLongThanN2_Time_21 : 16|16@1+ (1,0) [0|65535] "S"  PC
 SG_ S2P_Lmt8_OverCLongThanN3_Time_21 : 32|16@1+ (1,0) [0|65535] "S"  PC

BO_ 2417028694 S2P_Lmt8__22: 8 SBMU
 SG_ S2P_Lmt8_OverCLongThanN1_Time_22 : 0|16@1+ (1,0) [0|65535] "S"  PC
 SG_ S2P_Lmt8_OverCLongThanN2_Time_22 : 16|16@1+ (1,0) [0|65535] "S"  PC
 SG_ S2P_Lmt8_OverCLongThanN3_Time_22 : 32|16@1+ (1,0) [0|65535] "S"  PC

BO_ 2417028695 S2P_Lmt8__23: 8 SBMU
 SG_ S2P_Lmt8_OverCLongThanN1_Time_23 : 0|16@1+ (1,0) [0|65535] "S"  PC
 SG_ S2P_Lmt8_OverCLongThanN2_Time_23 : 16|16@1+ (1,0) [0|65535] "S"  PC
 SG_ S2P_Lmt8_OverCLongThanN3_Time_23 : 32|16@1+ (1,0) [0|65535] "S"  PC

BO_ 2417028696 S2P_Lmt8__24: 8 SBMU
 SG_ S2P_Lmt8_OverCLongThanN1_Time_24 : 0|16@1+ (1,0) [0|65535] "S"  PC
 SG_ S2P_Lmt8_OverCLongThanN2_Time_24 : 16|16@1+ (1,0) [0|65535] "S"  PC
 SG_ S2P_Lmt8_OverCLongThanN3_Time_24 : 32|16@1+ (1,0) [0|65535] "S"  PC

BO_ 2417028697 S2P_Lmt8__25: 8 SBMU
 SG_ S2P_Lmt8_OverCLongThanN1_Time_25 : 0|16@1+ (1,0) [0|65535] "S"  PC
 SG_ S2P_Lmt8_OverCLongThanN2_Time_25 : 16|16@1+ (1,0) [0|65535] "S"  PC
 SG_ S2P_Lmt8_OverCLongThanN3_Time_25 : 32|16@1+ (1,0) [0|65535] "S"  PC

BO_ 2417028698 S2P_Lmt8__26: 8 SBMU
 SG_ S2P_Lmt8_OverCLongThanN1_Time_26 : 0|16@1+ (1,0) [0|65535] "S"  PC
 SG_ S2P_Lmt8_OverCLongThanN2_Time_26 : 16|16@1+ (1,0) [0|65535] "S"  PC
 SG_ S2P_Lmt8_OverCLongThanN3_Time_26 : 32|16@1+ (1,0) [0|65535] "S"  PC

BO_ 2417028699 S2P_Lmt8__27: 8 SBMU
 SG_ S2P_Lmt8_OverCLongThanN1_Time_27 : 0|16@1+ (1,0) [0|65535] "S"  PC
 SG_ S2P_Lmt8_OverCLongThanN2_Time_27 : 16|16@1+ (1,0) [0|65535] "S"  PC
 SG_ S2P_Lmt8_OverCLongThanN3_Time_27 : 32|16@1+ (1,0) [0|65535] "S"  PC

BO_ 2417028700 S2P_Lmt8__28: 8 SBMU
 SG_ S2P_Lmt8_OverCLongThanN1_Time_28 : 0|16@1+ (1,0) [0|65535] "S"  PC
 SG_ S2P_Lmt8_OverCLongThanN2_Time_28 : 16|16@1+ (1,0) [0|65535] "S"  PC
 SG_ S2P_Lmt8_OverCLongThanN3_Time_28 : 32|16@1+ (1,0) [0|65535] "S"  PC

BO_ 2417028701 S2P_Lmt8__29: 8 SBMU
 SG_ S2P_Lmt8_OverCLongThanN1_Time_29 : 0|16@1+ (1,0) [0|65535] "S"  PC
 SG_ S2P_Lmt8_OverCLongThanN2_Time_29 : 16|16@1+ (1,0) [0|65535] "S"  PC
 SG_ S2P_Lmt8_OverCLongThanN3_Time_29 : 32|16@1+ (1,0) [0|65535] "S"  PC

BO_ 2417028702 S2P_Lmt8__30: 8 SBMU
 SG_ S2P_Lmt8_OverCLongThanN1_Time_30 : 0|16@1+ (1,0) [0|65535] "S"  PC
 SG_ S2P_Lmt8_OverCLongThanN2_Time_30 : 16|16@1+ (1,0) [0|65535] "S"  PC
 SG_ S2P_Lmt8_OverCLongThanN3_Time_30 : 32|16@1+ (1,0) [0|65535] "S"  PC

BO_ 2417028703 S2P_Lmt8__31: 8 SBMU
 SG_ S2P_Lmt8_OverCLongThanN1_Time_31 : 0|16@1+ (1,0) [0|65535] "S"  PC
 SG_ S2P_Lmt8_OverCLongThanN2_Time_31 : 16|16@1+ (1,0) [0|65535] "S"  PC
 SG_ S2P_Lmt8_OverCLongThanN3_Time_31 : 32|16@1+ (1,0) [0|65535] "S"  PC

BO_ 2417028704 S2P_Lmt8__32: 8 SBMU
 SG_ S2P_Lmt8_OverCLongThanN1_Time_32 : 0|16@1+ (1,0) [0|65535] "S"  PC
 SG_ S2P_Lmt8_OverCLongThanN2_Time_32 : 16|16@1+ (1,0) [0|65535] "S"  PC
 SG_ S2P_Lmt8_OverCLongThanN3_Time_32 : 32|16@1+ (1,0) [0|65535] "S"  PC

BO_ 2417028705 S2P_Lmt8__33: 8 SBMU
 SG_ S2P_Lmt8_OverCLongThanN1_Time_33 : 0|16@1+ (1,0) [0|65535] "S"  PC
 SG_ S2P_Lmt8_OverCLongThanN2_Time_33 : 16|16@1+ (1,0) [0|65535] "S"  PC
 SG_ S2P_Lmt8_OverCLongThanN3_Time_33 : 32|16@1+ (1,0) [0|65535] "S"  PC

BO_ 2417028706 S2P_Lmt8__34: 8 SBMU
 SG_ S2P_Lmt8_OverCLongThanN1_Time_34 : 0|16@1+ (1,0) [0|65535] "S"  PC
 SG_ S2P_Lmt8_OverCLongThanN2_Time_34 : 16|16@1+ (1,0) [0|65535] "S"  PC
 SG_ S2P_Lmt8_OverCLongThanN3_Time_34 : 32|16@1+ (1,0) [0|65535] "S"  PC

BO_ 2417028707 S2P_Lmt8__35: 8 SBMU
 SG_ S2P_Lmt8_OverCLongThanN1_Time_35 : 0|16@1+ (1,0) [0|65535] "S"  PC
 SG_ S2P_Lmt8_OverCLongThanN2_Time_35 : 16|16@1+ (1,0) [0|65535] "S"  PC
 SG_ S2P_Lmt8_OverCLongThanN3_Time_35 : 32|16@1+ (1,0) [0|65535] "S"  PC

BO_ 2417028708 S2P_Lmt8__36: 8 SBMU
 SG_ S2P_Lmt8_OverCLongThanN1_Time_36 : 0|16@1+ (1,0) [0|65535] "S"  PC
 SG_ S2P_Lmt8_OverCLongThanN2_Time_36 : 16|16@1+ (1,0) [0|65535] "S"  PC
 SG_ S2P_Lmt8_OverCLongThanN3_Time_36 : 32|16@1+ (1,0) [0|65535] "S"  PC

BO_ 2417028709 S2P_Lmt8__37: 8 SBMU
 SG_ S2P_Lmt8_OverCLongThanN1_Time_37 : 0|16@1+ (1,0) [0|65535] "S"  PC
 SG_ S2P_Lmt8_OverCLongThanN2_Time_37 : 16|16@1+ (1,0) [0|65535] "S"  PC
 SG_ S2P_Lmt8_OverCLongThanN3_Time_37 : 32|16@1+ (1,0) [0|65535] "S"  PC

BO_ 2417028710 S2P_Lmt8__38: 8 SBMU
 SG_ S2P_Lmt8_OverCLongThanN1_Time_38 : 0|16@1+ (1,0) [0|65535] "S"  PC
 SG_ S2P_Lmt8_OverCLongThanN2_Time_38 : 16|16@1+ (1,0) [0|65535] "S"  PC
 SG_ S2P_Lmt8_OverCLongThanN3_Time_38 : 32|16@1+ (1,0) [0|65535] "S"  PC

BO_ 2417028711 S2P_Lmt8__39: 8 SBMU
 SG_ S2P_Lmt8_OverCLongThanN1_Time_39 : 0|16@1+ (1,0) [0|65535] "S"  PC
 SG_ S2P_Lmt8_OverCLongThanN2_Time_39 : 16|16@1+ (1,0) [0|65535] "S"  PC
 SG_ S2P_Lmt8_OverCLongThanN3_Time_39 : 32|16@1+ (1,0) [0|65535] "S"  PC

BO_ 2417028712 S2P_Lmt8__40: 8 SBMU
 SG_ S2P_Lmt8_OverCLongThanN1_Time_40 : 0|16@1+ (1,0) [0|65535] "S"  PC
 SG_ S2P_Lmt8_OverCLongThanN2_Time_40 : 16|16@1+ (1,0) [0|65535] "S"  PC
 SG_ S2P_Lmt8_OverCLongThanN3_Time_40 : 32|16@1+ (1,0) [0|65535] "S"  PC

BO_ 2417028713 S2P_Lmt8__41: 8 SBMU
 SG_ S2P_Lmt8_OverCLongThanN1_Time_41 : 0|16@1+ (1,0) [0|65535] "S"  PC
 SG_ S2P_Lmt8_OverCLongThanN2_Time_41 : 16|16@1+ (1,0) [0|65535] "S"  PC
 SG_ S2P_Lmt8_OverCLongThanN3_Time_41 : 32|16@1+ (1,0) [0|65535] "S"  PC

BO_ 2417028714 S2P_Lmt8__42: 8 SBMU
 SG_ S2P_Lmt8_OverCLongThanN1_Time_42 : 0|16@1+ (1,0) [0|65535] "S"  PC
 SG_ S2P_Lmt8_OverCLongThanN2_Time_42 : 16|16@1+ (1,0) [0|65535] "S"  PC
 SG_ S2P_Lmt8_OverCLongThanN3_Time_42 : 32|16@1+ (1,0) [0|65535] "S"  PC

BO_ 2417028715 S2P_Lmt8__43: 8 SBMU
 SG_ S2P_Lmt8_OverCLongThanN1_Time_43 : 0|16@1+ (1,0) [0|65535] "S"  PC
 SG_ S2P_Lmt8_OverCLongThanN2_Time_43 : 16|16@1+ (1,0) [0|65535] "S"  PC
 SG_ S2P_Lmt8_OverCLongThanN3_Time_43 : 32|16@1+ (1,0) [0|65535] "S"  PC

BO_ 2417028716 S2P_Lmt8__44: 8 SBMU
 SG_ S2P_Lmt8_OverCLongThanN1_Time_44 : 0|16@1+ (1,0) [0|65535] "S"  PC
 SG_ S2P_Lmt8_OverCLongThanN2_Time_44 : 16|16@1+ (1,0) [0|65535] "S"  PC
 SG_ S2P_Lmt8_OverCLongThanN3_Time_44 : 32|16@1+ (1,0) [0|65535] "S"  PC

BO_ 2417028717 S2P_Lmt8__45: 8 SBMU
 SG_ S2P_Lmt8_OverCLongThanN1_Time_45 : 0|16@1+ (1,0) [0|65535] "S"  PC
 SG_ S2P_Lmt8_OverCLongThanN2_Time_45 : 16|16@1+ (1,0) [0|65535] "S"  PC
 SG_ S2P_Lmt8_OverCLongThanN3_Time_45 : 32|16@1+ (1,0) [0|65535] "S"  PC

BO_ 2417028718 S2P_Lmt8__46: 8 SBMU
 SG_ S2P_Lmt8_OverCLongThanN1_Time_46 : 0|16@1+ (1,0) [0|65535] "S"  PC
 SG_ S2P_Lmt8_OverCLongThanN2_Time_46 : 16|16@1+ (1,0) [0|65535] "S"  PC
 SG_ S2P_Lmt8_OverCLongThanN3_Time_46 : 32|16@1+ (1,0) [0|65535] "S"  PC

BO_ 2417028719 S2P_Lmt8__47: 8 SBMU
 SG_ S2P_Lmt8_OverCLongThanN1_Time_47 : 0|16@1+ (1,0) [0|65535] "S"  PC
 SG_ S2P_Lmt8_OverCLongThanN2_Time_47 : 16|16@1+ (1,0) [0|65535] "S"  PC
 SG_ S2P_Lmt8_OverCLongThanN3_Time_47 : 32|16@1+ (1,0) [0|65535] "S"  PC

BO_ 2417028720 S2P_Lmt8__48: 8 SBMU
 SG_ S2P_Lmt8_OverCLongThanN1_Time_48 : 0|16@1+ (1,0) [0|65535] "S"  PC
 SG_ S2P_Lmt8_OverCLongThanN2_Time_48 : 16|16@1+ (1,0) [0|65535] "S"  PC
 SG_ S2P_Lmt8_OverCLongThanN3_Time_48 : 32|16@1+ (1,0) [0|65535] "S"  PC

BO_ 2417028721 S2P_Lmt8__49: 8 SBMU
 SG_ S2P_Lmt8_OverCLongThanN1_Time_49 : 0|16@1+ (1,0) [0|65535] "S"  PC
 SG_ S2P_Lmt8_OverCLongThanN2_Time_49 : 16|16@1+ (1,0) [0|65535] "S"  PC
 SG_ S2P_Lmt8_OverCLongThanN3_Time_49 : 32|16@1+ (1,0) [0|65535] "S"  PC

BO_ 2417028722 S2P_Lmt8__50: 8 SBMU
 SG_ S2P_Lmt8_OverCLongThanN1_Time_50 : 0|16@1+ (1,0) [0|65535] "S"  PC
 SG_ S2P_Lmt8_OverCLongThanN2_Time_50 : 16|16@1+ (1,0) [0|65535] "S"  PC
 SG_ S2P_Lmt8_OverCLongThanN3_Time_50 : 32|16@1+ (1,0) [0|65535] "S"  PC

BO_ 2417028723 S2P_Lmt8__51: 8 SBMU
 SG_ S2P_Lmt8_OverCLongThanN1_Time_51 : 0|16@1+ (1,0) [0|65535] "S"  PC
 SG_ S2P_Lmt8_OverCLongThanN2_Time_51 : 16|16@1+ (1,0) [0|65535] "S"  PC
 SG_ S2P_Lmt8_OverCLongThanN3_Time_51 : 32|16@1+ (1,0) [0|65535] "S"  PC

BO_ 2417028724 S2P_Lmt8__52: 8 SBMU
 SG_ S2P_Lmt8_OverCLongThanN1_Time_52 : 0|16@1+ (1,0) [0|65535] "S"  PC
 SG_ S2P_Lmt8_OverCLongThanN2_Time_52 : 16|16@1+ (1,0) [0|65535] "S"  PC
 SG_ S2P_Lmt8_OverCLongThanN3_Time_52 : 32|16@1+ (1,0) [0|65535] "S"  PC

BO_ 2417028725 S2P_Lmt8__53: 8 SBMU
 SG_ S2P_Lmt8_OverCLongThanN1_Time_53 : 0|16@1+ (1,0) [0|65535] "S"  PC
 SG_ S2P_Lmt8_OverCLongThanN2_Time_53 : 16|16@1+ (1,0) [0|65535] "S"  PC
 SG_ S2P_Lmt8_OverCLongThanN3_Time_53 : 32|16@1+ (1,0) [0|65535] "S"  PC

BO_ 2417028726 S2P_Lmt8__54: 8 SBMU
 SG_ S2P_Lmt8_OverCLongThanN1_Time_54 : 0|16@1+ (1,0) [0|65535] "S"  PC
 SG_ S2P_Lmt8_OverCLongThanN2_Time_54 : 16|16@1+ (1,0) [0|65535] "S"  PC
 SG_ S2P_Lmt8_OverCLongThanN3_Time_54 : 32|16@1+ (1,0) [0|65535] "S"  PC

BO_ 2417028727 S2P_Lmt8__55: 8 SBMU
 SG_ S2P_Lmt8_OverCLongThanN1_Time_55 : 0|16@1+ (1,0) [0|65535] "S"  PC
 SG_ S2P_Lmt8_OverCLongThanN2_Time_55 : 16|16@1+ (1,0) [0|65535] "S"  PC
 SG_ S2P_Lmt8_OverCLongThanN3_Time_55 : 32|16@1+ (1,0) [0|65535] "S"  PC

BO_ 2417028728 S2P_Lmt8__56: 8 SBMU
 SG_ S2P_Lmt8_OverCLongThanN1_Time_56 : 0|16@1+ (1,0) [0|65535] "S"  PC
 SG_ S2P_Lmt8_OverCLongThanN2_Time_56 : 16|16@1+ (1,0) [0|65535] "S"  PC
 SG_ S2P_Lmt8_OverCLongThanN3_Time_56 : 32|16@1+ (1,0) [0|65535] "S"  PC

BO_ 2417028729 S2P_Lmt8__57: 8 SBMU
 SG_ S2P_Lmt8_OverCLongThanN1_Time_57 : 0|16@1+ (1,0) [0|65535] "S"  PC
 SG_ S2P_Lmt8_OverCLongThanN2_Time_57 : 16|16@1+ (1,0) [0|65535] "S"  PC
 SG_ S2P_Lmt8_OverCLongThanN3_Time_57 : 32|16@1+ (1,0) [0|65535] "S"  PC

BO_ 2417028730 S2P_Lmt8__58: 8 SBMU
 SG_ S2P_Lmt8_OverCLongThanN1_Time_58 : 0|16@1+ (1,0) [0|65535] "S"  PC
 SG_ S2P_Lmt8_OverCLongThanN2_Time_58 : 16|16@1+ (1,0) [0|65535] "S"  PC
 SG_ S2P_Lmt8_OverCLongThanN3_Time_58 : 32|16@1+ (1,0) [0|65535] "S"  PC

BO_ 2417028731 S2P_Lmt8__59: 8 SBMU
 SG_ S2P_Lmt8_OverCLongThanN1_Time_59 : 0|16@1+ (1,0) [0|65535] "S"  PC
 SG_ S2P_Lmt8_OverCLongThanN2_Time_59 : 16|16@1+ (1,0) [0|65535] "S"  PC
 SG_ S2P_Lmt8_OverCLongThanN3_Time_59 : 32|16@1+ (1,0) [0|65535] "S"  PC

BO_ 2417028732 S2P_Lmt8__60: 8 SBMU
 SG_ S2P_Lmt8_OverCLongThanN1_Time_60 : 0|16@1+ (1,0) [0|65535] "S"  PC
 SG_ S2P_Lmt8_OverCLongThanN2_Time_60 : 16|16@1+ (1,0) [0|65535] "S"  PC
 SG_ S2P_Lmt8_OverCLongThanN3_Time_60 : 32|16@1+ (1,0) [0|65535] "S"  PC

BO_ 2417028733 S2P_Lmt8__61: 8 SBMU
 SG_ S2P_Lmt8_OverCLongThanN1_Time_61 : 0|16@1+ (1,0) [0|65535] "S"  PC
 SG_ S2P_Lmt8_OverCLongThanN2_Time_61 : 16|16@1+ (1,0) [0|65535] "S"  PC
 SG_ S2P_Lmt8_OverCLongThanN3_Time_61 : 32|16@1+ (1,0) [0|65535] "S"  PC

BO_ 2417028734 S2P_Lmt8__62: 8 SBMU
 SG_ S2P_Lmt8_OverCLongThanN1_Time_62 : 0|16@1+ (1,0) [0|65535] "S"  PC
 SG_ S2P_Lmt8_OverCLongThanN2_Time_62 : 16|16@1+ (1,0) [0|65535] "S"  PC
 SG_ S2P_Lmt8_OverCLongThanN3_Time_62 : 32|16@1+ (1,0) [0|65535] "S"  PC

BO_ 2417028735 S2P_Lmt8__63: 8 SBMU
 SG_ S2P_Lmt8_OverCLongThanN1_Time_63 : 0|16@1+ (1,0) [0|65535] "S"  PC
 SG_ S2P_Lmt8_OverCLongThanN2_Time_63 : 16|16@1+ (1,0) [0|65535] "S"  PC
 SG_ S2P_Lmt8_OverCLongThanN3_Time_63 : 32|16@1+ (1,0) [0|65535] "S"  PC

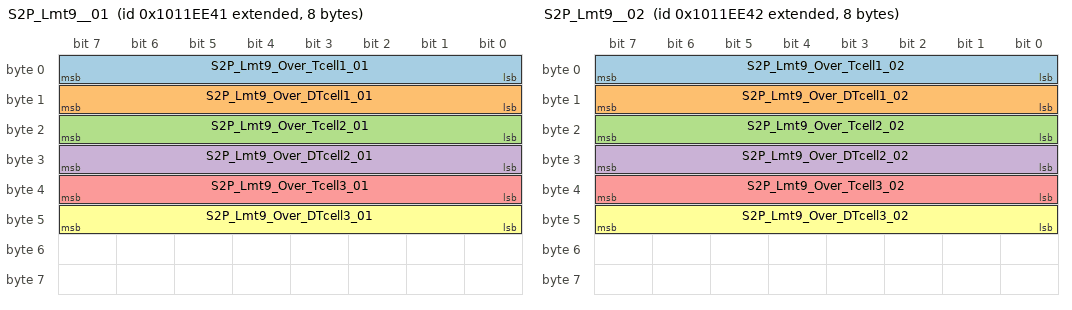
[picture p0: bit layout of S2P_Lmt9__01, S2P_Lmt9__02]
BO_ 2417094209 S2P_Lmt9__01: 8 SBMU
 SG_ S2P_Lmt9_Over_Tcell1_01 : 0|8@1+ (1,-50) [-50|205] "℃"  PC
 SG_ S2P_Lmt9_Over_DTcell1_01 : 8|8@1+ (1,-50) [-50|205] "℃"  PC
 SG_ S2P_Lmt9_Over_Tcell2_01 : 16|8@1+ (1,-50) [-50|205] "℃"  PC
 SG_ S2P_Lmt9_Over_DTcell2_01 : 24|8@1+ (1,-50) [-50|205] "℃"  PC
 SG_ S2P_Lmt9_Over_Tcell3_01 : 32|8@1+ (1,-50) [-50|205] "℃"  PC
 SG_ S2P_Lmt9_Over_DTcell3_01 : 40|8@1+ (1,-50) [-50|205] "℃"  PC

BO_ 2417094210 S2P_Lmt9__02: 8 SBMU
 SG_ S2P_Lmt9_Over_Tcell1_02 : 0|8@1+ (1,-50) [-50|205] "℃"  PC
 SG_ S2P_Lmt9_Over_DTcell1_02 : 8|8@1+ (1,-50) [-50|205] "℃"  PC
 SG_ S2P_Lmt9_Over_Tcell2_02 : 16|8@1+ (1,-50) [-50|205] "℃"  PC
 SG_ S2P_Lmt9_Over_DTcell2_02 : 24|8@1+ (1,-50) [-50|205] "℃"  PC
 SG_ S2P_Lmt9_Over_Tcell3_02 : 32|8@1+ (1,-50) [-50|205] "℃"  PC
 SG_ S2P_Lmt9_Over_DTcell3_02 : 40|8@1+ (1,-50) [-50|205] "℃"  PC

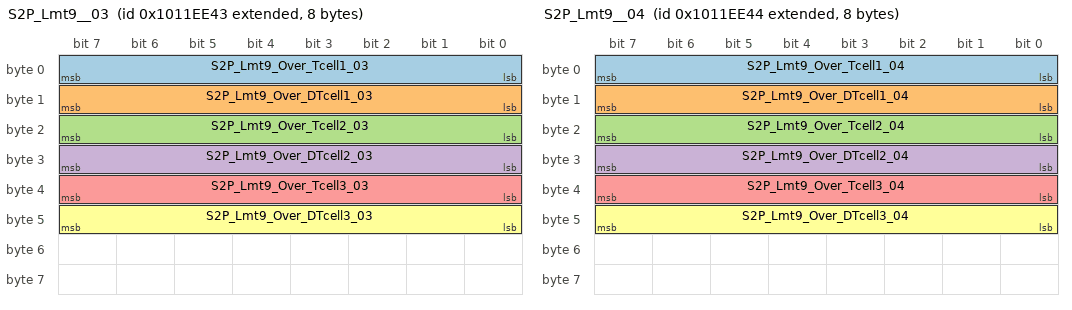
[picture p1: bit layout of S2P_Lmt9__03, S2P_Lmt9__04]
BO_ 2417094211 S2P_Lmt9__03: 8 SBMU
 SG_ S2P_Lmt9_Over_Tcell1_03 : 0|8@1+ (1,-50) [-50|205] "℃"  PC
 SG_ S2P_Lmt9_Over_DTcell1_03 : 8|8@1+ (1,-50) [-50|205] "℃"  PC
 SG_ S2P_Lmt9_Over_Tcell2_03 : 16|8@1+ (1,-50) [-50|205] "℃"  PC
 SG_ S2P_Lmt9_Over_DTcell2_03 : 24|8@1+ (1,-50) [-50|205] "℃"  PC
 SG_ S2P_Lmt9_Over_Tcell3_03 : 32|8@1+ (1,-50) [-50|205] "℃"  PC
 SG_ S2P_Lmt9_Over_DTcell3_03 : 40|8@1+ (1,-50) [-50|205] "℃"  PC

BO_ 2417094212 S2P_Lmt9__04: 8 SBMU
 SG_ S2P_Lmt9_Over_Tcell1_04 : 0|8@1+ (1,-50) [-50|205] "℃"  PC
 SG_ S2P_Lmt9_Over_DTcell1_04 : 8|8@1+ (1,-50) [-50|205] "℃"  PC
 SG_ S2P_Lmt9_Over_Tcell2_04 : 16|8@1+ (1,-50) [-50|205] "℃"  PC
 SG_ S2P_Lmt9_Over_DTcell2_04 : 24|8@1+ (1,-50) [-50|205] "℃"  PC
 SG_ S2P_Lmt9_Over_Tcell3_04 : 32|8@1+ (1,-50) [-50|205] "℃"  PC
 SG_ S2P_Lmt9_Over_DTcell3_04 : 40|8@1+ (1,-50) [-50|205] "℃"  PC

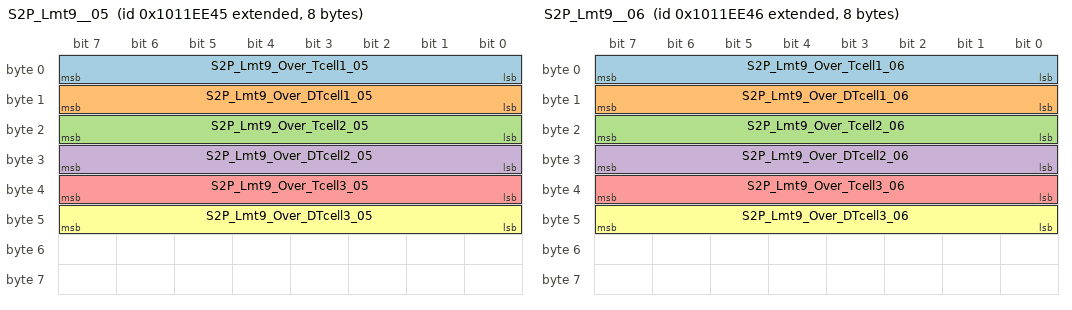
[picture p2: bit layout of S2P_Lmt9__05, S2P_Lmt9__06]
BO_ 2417094213 S2P_Lmt9__05: 8 SBMU
 SG_ S2P_Lmt9_Over_Tcell1_05 : 0|8@1+ (1,-50) [-50|205] "℃"  PC
 SG_ S2P_Lmt9_Over_DTcell1_05 : 8|8@1+ (1,-50) [-50|205] "℃"  PC
 SG_ S2P_Lmt9_Over_Tcell2_05 : 16|8@1+ (1,-50) [-50|205] "℃"  PC
 SG_ S2P_Lmt9_Over_DTcell2_05 : 24|8@1+ (1,-50) [-50|205] "℃"  PC
 SG_ S2P_Lmt9_Over_Tcell3_05 : 32|8@1+ (1,-50) [-50|205] "℃"  PC
 SG_ S2P_Lmt9_Over_DTcell3_05 : 40|8@1+ (1,-50) [-50|205] "℃"  PC

BO_ 2417094214 S2P_Lmt9__06: 8 SBMU
 SG_ S2P_Lmt9_Over_Tcell1_06 : 0|8@1+ (1,-50) [-50|205] "℃"  PC
 SG_ S2P_Lmt9_Over_DTcell1_06 : 8|8@1+ (1,-50) [-50|205] "℃"  PC
 SG_ S2P_Lmt9_Over_Tcell2_06 : 16|8@1+ (1,-50) [-50|205] "℃"  PC
 SG_ S2P_Lmt9_Over_DTcell2_06 : 24|8@1+ (1,-50) [-50|205] "℃"  PC
 SG_ S2P_Lmt9_Over_Tcell3_06 : 32|8@1+ (1,-50) [-50|205] "℃"  PC
 SG_ S2P_Lmt9_Over_DTcell3_06 : 40|8@1+ (1,-50) [-50|205] "℃"  PC

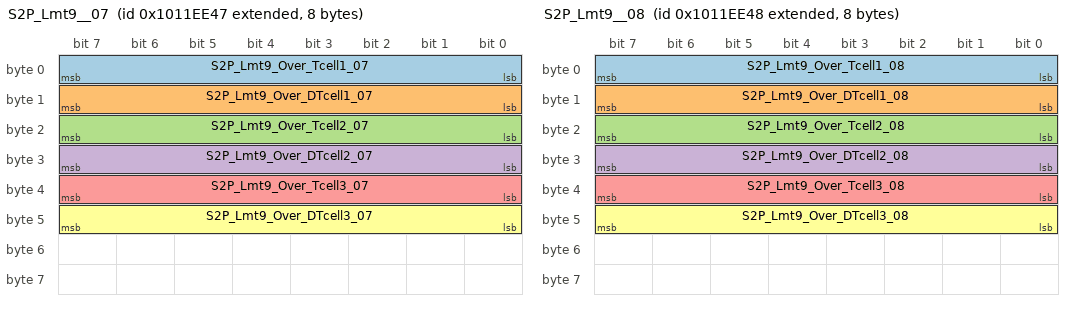
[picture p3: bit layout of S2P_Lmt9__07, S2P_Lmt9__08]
BO_ 2417094215 S2P_Lmt9__07: 8 SBMU
 SG_ S2P_Lmt9_Over_Tcell1_07 : 0|8@1+ (1,-50) [-50|205] "℃"  PC
 SG_ S2P_Lmt9_Over_DTcell1_07 : 8|8@1+ (1,-50) [-50|205] "℃"  PC
 SG_ S2P_Lmt9_Over_Tcell2_07 : 16|8@1+ (1,-50) [-50|205] "℃"  PC
 SG_ S2P_Lmt9_Over_DTcell2_07 : 24|8@1+ (1,-50) [-50|205] "℃"  PC
 SG_ S2P_Lmt9_Over_Tcell3_07 : 32|8@1+ (1,-50) [-50|205] "℃"  PC
 SG_ S2P_Lmt9_Over_DTcell3_07 : 40|8@1+ (1,-50) [-50|205] "℃"  PC

BO_ 2417094216 S2P_Lmt9__08: 8 SBMU
 SG_ S2P_Lmt9_Over_Tcell1_08 : 0|8@1+ (1,-50) [-50|205] "℃"  PC
 SG_ S2P_Lmt9_Over_DTcell1_08 : 8|8@1+ (1,-50) [-50|205] "℃"  PC
 SG_ S2P_Lmt9_Over_Tcell2_08 : 16|8@1+ (1,-50) [-50|205] "℃"  PC
 SG_ S2P_Lmt9_Over_DTcell2_08 : 24|8@1+ (1,-50) [-50|205] "℃"  PC
 SG_ S2P_Lmt9_Over_Tcell3_08 : 32|8@1+ (1,-50) [-50|205] "℃"  PC
 SG_ S2P_Lmt9_Over_DTcell3_08 : 40|8@1+ (1,-50) [-50|205] "℃"  PC

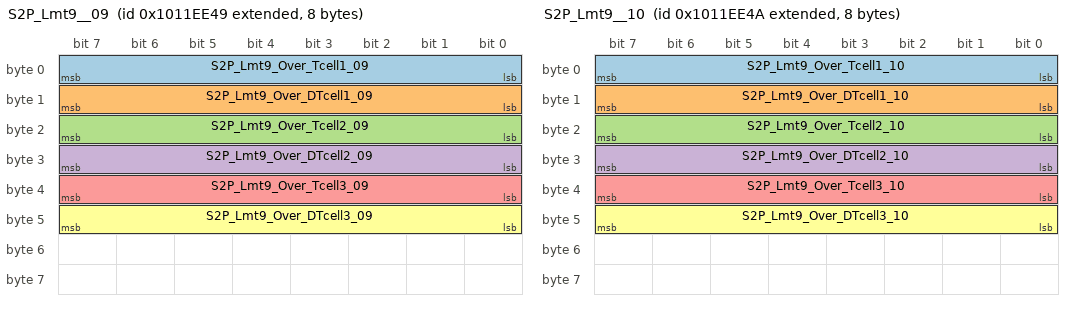
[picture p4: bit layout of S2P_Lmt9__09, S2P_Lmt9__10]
BO_ 2417094217 S2P_Lmt9__09: 8 SBMU
 SG_ S2P_Lmt9_Over_Tcell1_09 : 0|8@1+ (1,-50) [-50|205] "℃"  PC
 SG_ S2P_Lmt9_Over_DTcell1_09 : 8|8@1+ (1,-50) [-50|205] "℃"  PC
 SG_ S2P_Lmt9_Over_Tcell2_09 : 16|8@1+ (1,-50) [-50|205] "℃"  PC
 SG_ S2P_Lmt9_Over_DTcell2_09 : 24|8@1+ (1,-50) [-50|205] "℃"  PC
 SG_ S2P_Lmt9_Over_Tcell3_09 : 32|8@1+ (1,-50) [-50|205] "℃"  PC
 SG_ S2P_Lmt9_Over_DTcell3_09 : 40|8@1+ (1,-50) [-50|205] "℃"  PC

BO_ 2417094218 S2P_Lmt9__10: 8 SBMU
 SG_ S2P_Lmt9_Over_Tcell1_10 : 0|8@1+ (1,-50) [-50|205] "℃"  PC
 SG_ S2P_Lmt9_Over_DTcell1_10 : 8|8@1+ (1,-50) [-50|205] "℃"  PC
 SG_ S2P_Lmt9_Over_Tcell2_10 : 16|8@1+ (1,-50) [-50|205] "℃"  PC
 SG_ S2P_Lmt9_Over_DTcell2_10 : 24|8@1+ (1,-50) [-50|205] "℃"  PC
 SG_ S2P_Lmt9_Over_Tcell3_10 : 32|8@1+ (1,-50) [-50|205] "℃"  PC
 SG_ S2P_Lmt9_Over_DTcell3_10 : 40|8@1+ (1,-50) [-50|205] "℃"  PC

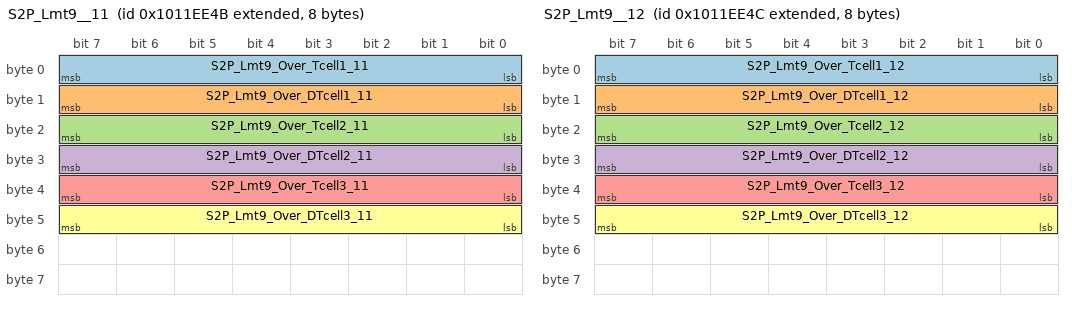
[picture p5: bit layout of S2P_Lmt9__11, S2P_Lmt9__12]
BO_ 2417094219 S2P_Lmt9__11: 8 SBMU
 SG_ S2P_Lmt9_Over_Tcell1_11 : 0|8@1+ (1,-50) [-50|205] "℃"  PC
 SG_ S2P_Lmt9_Over_DTcell1_11 : 8|8@1+ (1,-50) [-50|205] "℃"  PC
 SG_ S2P_Lmt9_Over_Tcell2_11 : 16|8@1+ (1,-50) [-50|205] "℃"  PC
 SG_ S2P_Lmt9_Over_DTcell2_11 : 24|8@1+ (1,-50) [-50|205] "℃"  PC
 SG_ S2P_Lmt9_Over_Tcell3_11 : 32|8@1+ (1,-50) [-50|205] "℃"  PC
 SG_ S2P_Lmt9_Over_DTcell3_11 : 40|8@1+ (1,-50) [-50|205] "℃"  PC

BO_ 2417094220 S2P_Lmt9__12: 8 SBMU
 SG_ S2P_Lmt9_Over_Tcell1_12 : 0|8@1+ (1,-50) [-50|205] "℃"  PC
 SG_ S2P_Lmt9_Over_DTcell1_12 : 8|8@1+ (1,-50) [-50|205] "℃"  PC
 SG_ S2P_Lmt9_Over_Tcell2_12 : 16|8@1+ (1,-50) [-50|205] "℃"  PC
 SG_ S2P_Lmt9_Over_DTcell2_12 : 24|8@1+ (1,-50) [-50|205] "℃"  PC
 SG_ S2P_Lmt9_Over_Tcell3_12 : 32|8@1+ (1,-50) [-50|205] "℃"  PC
 SG_ S2P_Lmt9_Over_DTcell3_12 : 40|8@1+ (1,-50) [-50|205] "℃"  PC

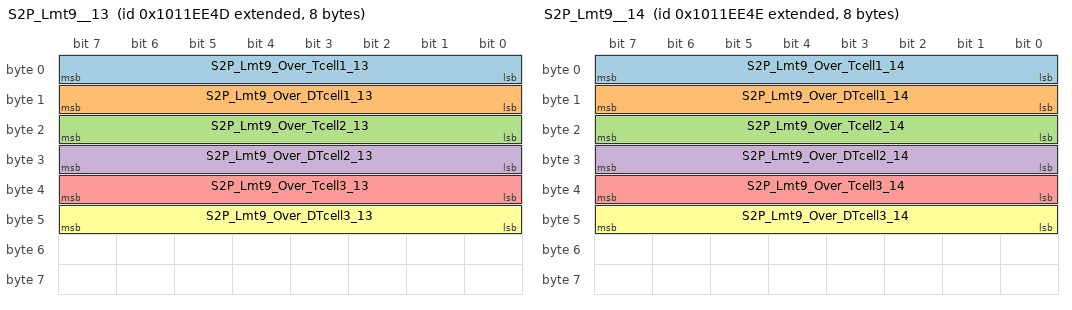
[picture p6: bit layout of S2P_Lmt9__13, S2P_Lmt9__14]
BO_ 2417094221 S2P_Lmt9__13: 8 SBMU
 SG_ S2P_Lmt9_Over_Tcell1_13 : 0|8@1+ (1,-50) [-50|205] "℃"  PC
 SG_ S2P_Lmt9_Over_DTcell1_13 : 8|8@1+ (1,-50) [-50|205] "℃"  PC
 SG_ S2P_Lmt9_Over_Tcell2_13 : 16|8@1+ (1,-50) [-50|205] "℃"  PC
 SG_ S2P_Lmt9_Over_DTcell2_13 : 24|8@1+ (1,-50) [-50|205] "℃"  PC
 SG_ S2P_Lmt9_Over_Tcell3_13 : 32|8@1+ (1,-50) [-50|205] "℃"  PC
 SG_ S2P_Lmt9_Over_DTcell3_13 : 40|8@1+ (1,-50) [-50|205] "℃"  PC

BO_ 2417094222 S2P_Lmt9__14: 8 SBMU
 SG_ S2P_Lmt9_Over_Tcell1_14 : 0|8@1+ (1,-50) [-50|205] "℃"  PC
 SG_ S2P_Lmt9_Over_DTcell1_14 : 8|8@1+ (1,-50) [-50|205] "℃"  PC
 SG_ S2P_Lmt9_Over_Tcell2_14 : 16|8@1+ (1,-50) [-50|205] "℃"  PC
 SG_ S2P_Lmt9_Over_DTcell2_14 : 24|8@1+ (1,-50) [-50|205] "℃"  PC
 SG_ S2P_Lmt9_Over_Tcell3_14 : 32|8@1+ (1,-50) [-50|205] "℃"  PC
 SG_ S2P_Lmt9_Over_DTcell3_14 : 40|8@1+ (1,-50) [-50|205] "℃"  PC

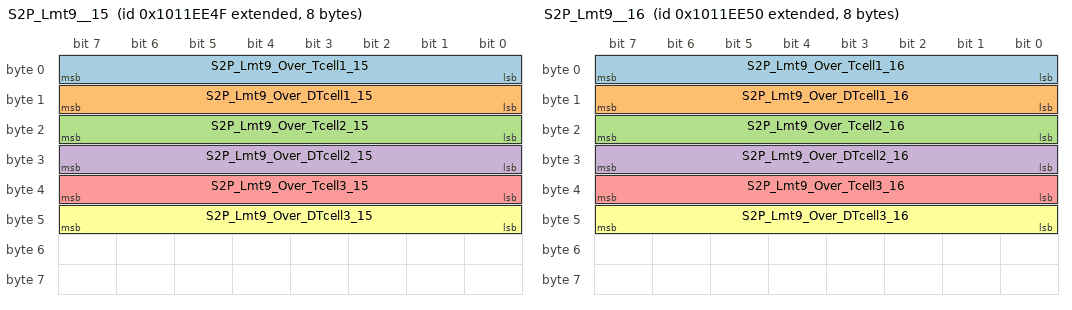
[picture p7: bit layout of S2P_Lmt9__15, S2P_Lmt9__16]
BO_ 2417094223 S2P_Lmt9__15: 8 SBMU
 SG_ S2P_Lmt9_Over_Tcell1_15 : 0|8@1+ (1,-50) [-50|205] "℃"  PC
 SG_ S2P_Lmt9_Over_DTcell1_15 : 8|8@1+ (1,-50) [-50|205] "℃"  PC
 SG_ S2P_Lmt9_Over_Tcell2_15 : 16|8@1+ (1,-50) [-50|205] "℃"  PC
 SG_ S2P_Lmt9_Over_DTcell2_15 : 24|8@1+ (1,-50) [-50|205] "℃"  PC
 SG_ S2P_Lmt9_Over_Tcell3_15 : 32|8@1+ (1,-50) [-50|205] "℃"  PC
 SG_ S2P_Lmt9_Over_DTcell3_15 : 40|8@1+ (1,-50) [-50|205] "℃"  PC

BO_ 2417094224 S2P_Lmt9__16: 8 SBMU
 SG_ S2P_Lmt9_Over_Tcell1_16 : 0|8@1+ (1,-50) [-50|205] "℃"  PC
 SG_ S2P_Lmt9_Over_DTcell1_16 : 8|8@1+ (1,-50) [-50|205] "℃"  PC
 SG_ S2P_Lmt9_Over_Tcell2_16 : 16|8@1+ (1,-50) [-50|205] "℃"  PC
 SG_ S2P_Lmt9_Over_DTcell2_16 : 24|8@1+ (1,-50) [-50|205] "℃"  PC
 SG_ S2P_Lmt9_Over_Tcell3_16 : 32|8@1+ (1,-50) [-50|205] "℃"  PC
 SG_ S2P_Lmt9_Over_DTcell3_16 : 40|8@1+ (1,-50) [-50|205] "℃"  PC

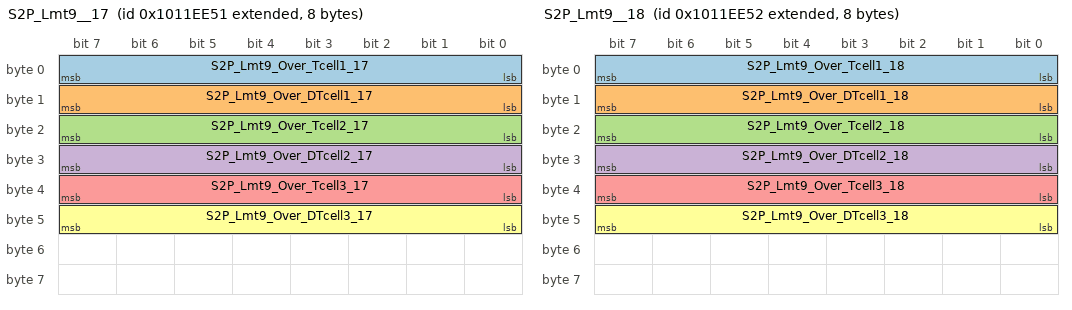
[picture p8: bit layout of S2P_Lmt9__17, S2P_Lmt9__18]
BO_ 2417094225 S2P_Lmt9__17: 8 SBMU
 SG_ S2P_Lmt9_Over_Tcell1_17 : 0|8@1+ (1,-50) [-50|205] "℃"  PC
 SG_ S2P_Lmt9_Over_DTcell1_17 : 8|8@1+ (1,-50) [-50|205] "℃"  PC
 SG_ S2P_Lmt9_Over_Tcell2_17 : 16|8@1+ (1,-50) [-50|205] "℃"  PC
 SG_ S2P_Lmt9_Over_DTcell2_17 : 24|8@1+ (1,-50) [-50|205] "℃"  PC
 SG_ S2P_Lmt9_Over_Tcell3_17 : 32|8@1+ (1,-50) [-50|205] "℃"  PC
 SG_ S2P_Lmt9_Over_DTcell3_17 : 40|8@1+ (1,-50) [-50|205] "℃"  PC

BO_ 2417094226 S2P_Lmt9__18: 8 SBMU
 SG_ S2P_Lmt9_Over_Tcell1_18 : 0|8@1+ (1,-50) [-50|205] "℃"  PC
 SG_ S2P_Lmt9_Over_DTcell1_18 : 8|8@1+ (1,-50) [-50|205] "℃"  PC
 SG_ S2P_Lmt9_Over_Tcell2_18 : 16|8@1+ (1,-50) [-50|205] "℃"  PC
 SG_ S2P_Lmt9_Over_DTcell2_18 : 24|8@1+ (1,-50) [-50|205] "℃"  PC
 SG_ S2P_Lmt9_Over_Tcell3_18 : 32|8@1+ (1,-50) [-50|205] "℃"  PC
 SG_ S2P_Lmt9_Over_DTcell3_18 : 40|8@1+ (1,-50) [-50|205] "℃"  PC

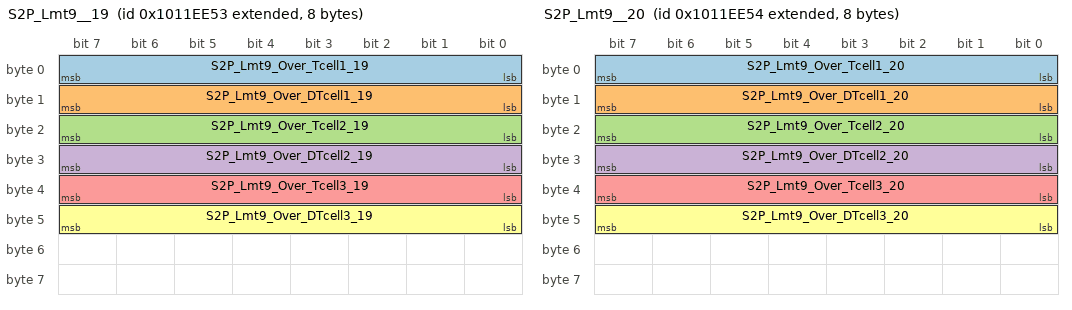
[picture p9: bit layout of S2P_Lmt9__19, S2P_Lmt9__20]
BO_ 2417094227 S2P_Lmt9__19: 8 SBMU
 SG_ S2P_Lmt9_Over_Tcell1_19 : 0|8@1+ (1,-50) [-50|205] "℃"  PC
 SG_ S2P_Lmt9_Over_DTcell1_19 : 8|8@1+ (1,-50) [-50|205] "℃"  PC
 SG_ S2P_Lmt9_Over_Tcell2_19 : 16|8@1+ (1,-50) [-50|205] "℃"  PC
 SG_ S2P_Lmt9_Over_DTcell2_19 : 24|8@1+ (1,-50) [-50|205] "℃"  PC
 SG_ S2P_Lmt9_Over_Tcell3_19 : 32|8@1+ (1,-50) [-50|205] "℃"  PC
 SG_ S2P_Lmt9_Over_DTcell3_19 : 40|8@1+ (1,-50) [-50|205] "℃"  PC

BO_ 2417094228 S2P_Lmt9__20: 8 SBMU
 SG_ S2P_Lmt9_Over_Tcell1_20 : 0|8@1+ (1,-50) [-50|205] "℃"  PC
 SG_ S2P_Lmt9_Over_DTcell1_20 : 8|8@1+ (1,-50) [-50|205] "℃"  PC
 SG_ S2P_Lmt9_Over_Tcell2_20 : 16|8@1+ (1,-50) [-50|205] "℃"  PC
 SG_ S2P_Lmt9_Over_DTcell2_20 : 24|8@1+ (1,-50) [-50|205] "℃"  PC
 SG_ S2P_Lmt9_Over_Tcell3_20 : 32|8@1+ (1,-50) [-50|205] "℃"  PC
 SG_ S2P_Lmt9_Over_DTcell3_20 : 40|8@1+ (1,-50) [-50|205] "℃"  PC

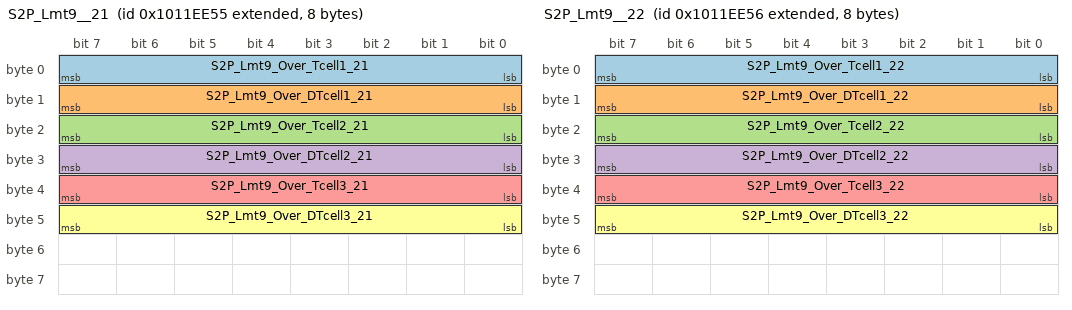
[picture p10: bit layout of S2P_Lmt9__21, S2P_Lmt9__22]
BO_ 2417094229 S2P_Lmt9__21: 8 SBMU
 SG_ S2P_Lmt9_Over_Tcell1_21 : 0|8@1+ (1,-50) [-50|205] "℃"  PC
 SG_ S2P_Lmt9_Over_DTcell1_21 : 8|8@1+ (1,-50) [-50|205] "℃"  PC
 SG_ S2P_Lmt9_Over_Tcell2_21 : 16|8@1+ (1,-50) [-50|205] "℃"  PC
 SG_ S2P_Lmt9_Over_DTcell2_21 : 24|8@1+ (1,-50) [-50|205] "℃"  PC
 SG_ S2P_Lmt9_Over_Tcell3_21 : 32|8@1+ (1,-50) [-50|205] "℃"  PC
 SG_ S2P_Lmt9_Over_DTcell3_21 : 40|8@1+ (1,-50) [-50|205] "℃"  PC

BO_ 2417094230 S2P_Lmt9__22: 8 SBMU
 SG_ S2P_Lmt9_Over_Tcell1_22 : 0|8@1+ (1,-50) [-50|205] "℃"  PC
 SG_ S2P_Lmt9_Over_DTcell1_22 : 8|8@1+ (1,-50) [-50|205] "℃"  PC
 SG_ S2P_Lmt9_Over_Tcell2_22 : 16|8@1+ (1,-50) [-50|205] "℃"  PC
 SG_ S2P_Lmt9_Over_DTcell2_22 : 24|8@1+ (1,-50) [-50|205] "℃"  PC
 SG_ S2P_Lmt9_Over_Tcell3_22 : 32|8@1+ (1,-50) [-50|205] "℃"  PC
 SG_ S2P_Lmt9_Over_DTcell3_22 : 40|8@1+ (1,-50) [-50|205] "℃"  PC

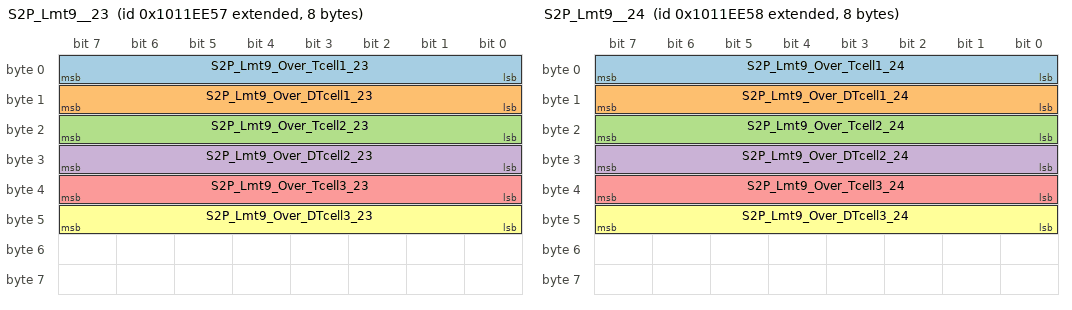
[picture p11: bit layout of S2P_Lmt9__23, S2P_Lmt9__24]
BO_ 2417094231 S2P_Lmt9__23: 8 SBMU
 SG_ S2P_Lmt9_Over_Tcell1_23 : 0|8@1+ (1,-50) [-50|205] "℃"  PC
 SG_ S2P_Lmt9_Over_DTcell1_23 : 8|8@1+ (1,-50) [-50|205] "℃"  PC
 SG_ S2P_Lmt9_Over_Tcell2_23 : 16|8@1+ (1,-50) [-50|205] "℃"  PC
 SG_ S2P_Lmt9_Over_DTcell2_23 : 24|8@1+ (1,-50) [-50|205] "℃"  PC
 SG_ S2P_Lmt9_Over_Tcell3_23 : 32|8@1+ (1,-50) [-50|205] "℃"  PC
 SG_ S2P_Lmt9_Over_DTcell3_23 : 40|8@1+ (1,-50) [-50|205] "℃"  PC

BO_ 2417094232 S2P_Lmt9__24: 8 SBMU
 SG_ S2P_Lmt9_Over_Tcell1_24 : 0|8@1+ (1,-50) [-50|205] "℃"  PC
 SG_ S2P_Lmt9_Over_DTcell1_24 : 8|8@1+ (1,-50) [-50|205] "℃"  PC
 SG_ S2P_Lmt9_Over_Tcell2_24 : 16|8@1+ (1,-50) [-50|205] "℃"  PC
 SG_ S2P_Lmt9_Over_DTcell2_24 : 24|8@1+ (1,-50) [-50|205] "℃"  PC
 SG_ S2P_Lmt9_Over_Tcell3_24 : 32|8@1+ (1,-50) [-50|205] "℃"  PC
 SG_ S2P_Lmt9_Over_DTcell3_24 : 40|8@1+ (1,-50) [-50|205] "℃"  PC

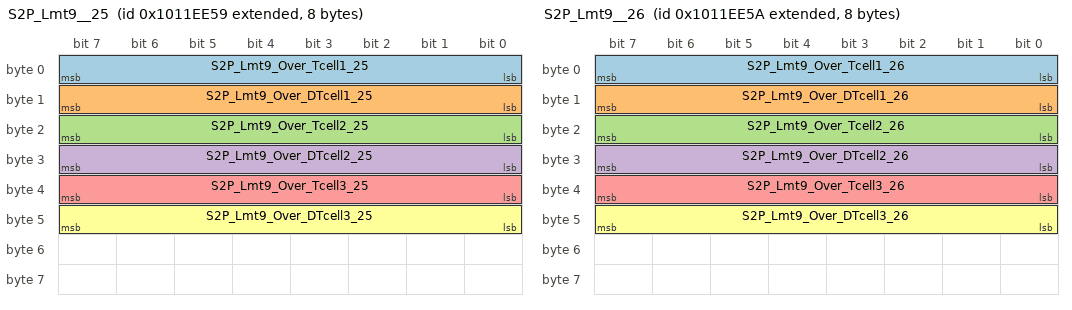
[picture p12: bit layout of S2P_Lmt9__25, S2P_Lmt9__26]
BO_ 2417094233 S2P_Lmt9__25: 8 SBMU
 SG_ S2P_Lmt9_Over_Tcell1_25 : 0|8@1+ (1,-50) [-50|205] "℃"  PC
 SG_ S2P_Lmt9_Over_DTcell1_25 : 8|8@1+ (1,-50) [-50|205] "℃"  PC
 SG_ S2P_Lmt9_Over_Tcell2_25 : 16|8@1+ (1,-50) [-50|205] "℃"  PC
 SG_ S2P_Lmt9_Over_DTcell2_25 : 24|8@1+ (1,-50) [-50|205] "℃"  PC
 SG_ S2P_Lmt9_Over_Tcell3_25 : 32|8@1+ (1,-50) [-50|205] "℃"  PC
 SG_ S2P_Lmt9_Over_DTcell3_25 : 40|8@1+ (1,-50) [-50|205] "℃"  PC

BO_ 2417094234 S2P_Lmt9__26: 8 SBMU
 SG_ S2P_Lmt9_Over_Tcell1_26 : 0|8@1+ (1,-50) [-50|205] "℃"  PC
 SG_ S2P_Lmt9_Over_DTcell1_26 : 8|8@1+ (1,-50) [-50|205] "℃"  PC
 SG_ S2P_Lmt9_Over_Tcell2_26 : 16|8@1+ (1,-50) [-50|205] "℃"  PC
 SG_ S2P_Lmt9_Over_DTcell2_26 : 24|8@1+ (1,-50) [-50|205] "℃"  PC
 SG_ S2P_Lmt9_Over_Tcell3_26 : 32|8@1+ (1,-50) [-50|205] "℃"  PC
 SG_ S2P_Lmt9_Over_DTcell3_26 : 40|8@1+ (1,-50) [-50|205] "℃"  PC

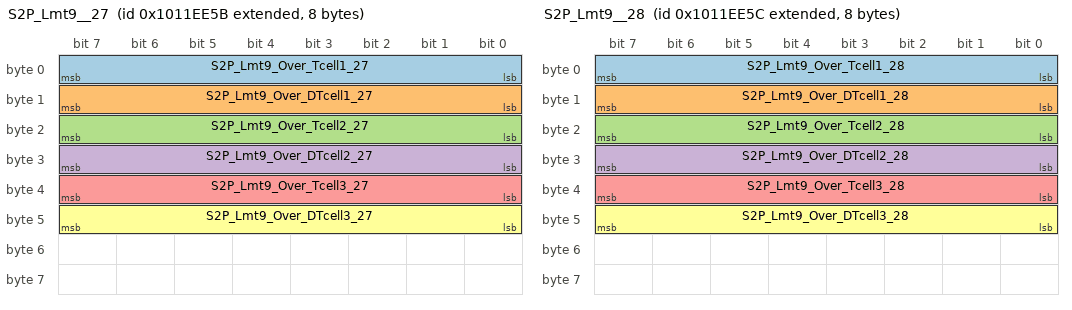
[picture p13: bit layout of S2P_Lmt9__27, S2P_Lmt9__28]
BO_ 2417094235 S2P_Lmt9__27: 8 SBMU
 SG_ S2P_Lmt9_Over_Tcell1_27 : 0|8@1+ (1,-50) [-50|205] "℃"  PC
 SG_ S2P_Lmt9_Over_DTcell1_27 : 8|8@1+ (1,-50) [-50|205] "℃"  PC
 SG_ S2P_Lmt9_Over_Tcell2_27 : 16|8@1+ (1,-50) [-50|205] "℃"  PC
 SG_ S2P_Lmt9_Over_DTcell2_27 : 24|8@1+ (1,-50) [-50|205] "℃"  PC
 SG_ S2P_Lmt9_Over_Tcell3_27 : 32|8@1+ (1,-50) [-50|205] "℃"  PC
 SG_ S2P_Lmt9_Over_DTcell3_27 : 40|8@1+ (1,-50) [-50|205] "℃"  PC

BO_ 2417094236 S2P_Lmt9__28: 8 SBMU
 SG_ S2P_Lmt9_Over_Tcell1_28 : 0|8@1+ (1,-50) [-50|205] "℃"  PC
 SG_ S2P_Lmt9_Over_DTcell1_28 : 8|8@1+ (1,-50) [-50|205] "℃"  PC
 SG_ S2P_Lmt9_Over_Tcell2_28 : 16|8@1+ (1,-50) [-50|205] "℃"  PC
 SG_ S2P_Lmt9_Over_DTcell2_28 : 24|8@1+ (1,-50) [-50|205] "℃"  PC
 SG_ S2P_Lmt9_Over_Tcell3_28 : 32|8@1+ (1,-50) [-50|205] "℃"  PC
 SG_ S2P_Lmt9_Over_DTcell3_28 : 40|8@1+ (1,-50) [-50|205] "℃"  PC

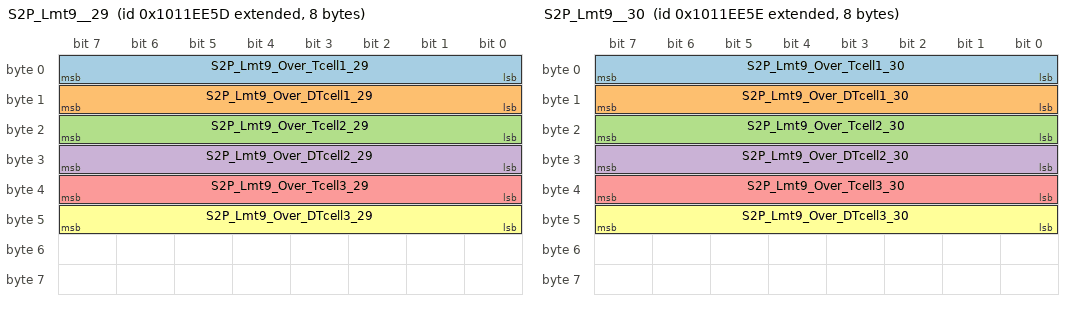
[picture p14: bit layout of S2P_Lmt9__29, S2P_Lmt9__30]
BO_ 2417094237 S2P_Lmt9__29: 8 SBMU
 SG_ S2P_Lmt9_Over_Tcell1_29 : 0|8@1+ (1,-50) [-50|205] "℃"  PC
 SG_ S2P_Lmt9_Over_DTcell1_29 : 8|8@1+ (1,-50) [-50|205] "℃"  PC
 SG_ S2P_Lmt9_Over_Tcell2_29 : 16|8@1+ (1,-50) [-50|205] "℃"  PC
 SG_ S2P_Lmt9_Over_DTcell2_29 : 24|8@1+ (1,-50) [-50|205] "℃"  PC
 SG_ S2P_Lmt9_Over_Tcell3_29 : 32|8@1+ (1,-50) [-50|205] "℃"  PC
 SG_ S2P_Lmt9_Over_DTcell3_29 : 40|8@1+ (1,-50) [-50|205] "℃"  PC

BO_ 2417094238 S2P_Lmt9__30: 8 SBMU
 SG_ S2P_Lmt9_Over_Tcell1_30 : 0|8@1+ (1,-50) [-50|205] "℃"  PC
 SG_ S2P_Lmt9_Over_DTcell1_30 : 8|8@1+ (1,-50) [-50|205] "℃"  PC
 SG_ S2P_Lmt9_Over_Tcell2_30 : 16|8@1+ (1,-50) [-50|205] "℃"  PC
 SG_ S2P_Lmt9_Over_DTcell2_30 : 24|8@1+ (1,-50) [-50|205] "℃"  PC
 SG_ S2P_Lmt9_Over_Tcell3_30 : 32|8@1+ (1,-50) [-50|205] "℃"  PC
 SG_ S2P_Lmt9_Over_DTcell3_30 : 40|8@1+ (1,-50) [-50|205] "℃"  PC

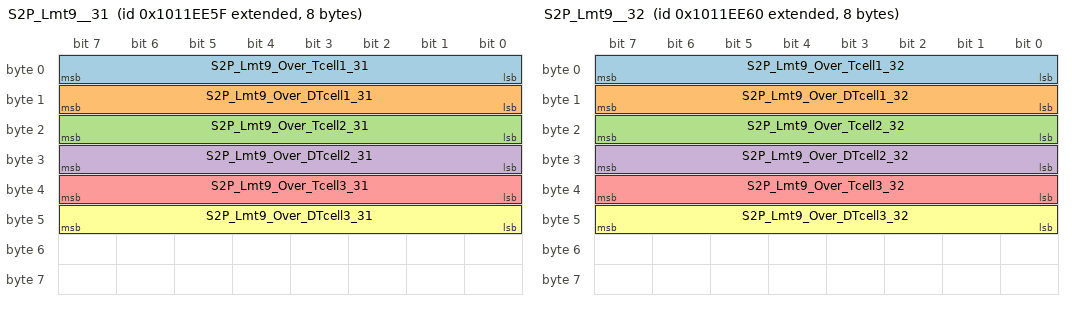
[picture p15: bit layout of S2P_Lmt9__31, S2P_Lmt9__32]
BO_ 2417094239 S2P_Lmt9__31: 8 SBMU
 SG_ S2P_Lmt9_Over_Tcell1_31 : 0|8@1+ (1,-50) [-50|205] "℃"  PC
 SG_ S2P_Lmt9_Over_DTcell1_31 : 8|8@1+ (1,-50) [-50|205] "℃"  PC
 SG_ S2P_Lmt9_Over_Tcell2_31 : 16|8@1+ (1,-50) [-50|205] "℃"  PC
 SG_ S2P_Lmt9_Over_DTcell2_31 : 24|8@1+ (1,-50) [-50|205] "℃"  PC
 SG_ S2P_Lmt9_Over_Tcell3_31 : 32|8@1+ (1,-50) [-50|205] "℃"  PC
 SG_ S2P_Lmt9_Over_DTcell3_31 : 40|8@1+ (1,-50) [-50|205] "℃"  PC

BO_ 2417094240 S2P_Lmt9__32: 8 SBMU
 SG_ S2P_Lmt9_Over_Tcell1_32 : 0|8@1+ (1,-50) [-50|205] "℃"  PC
 SG_ S2P_Lmt9_Over_DTcell1_32 : 8|8@1+ (1,-50) [-50|205] "℃"  PC
 SG_ S2P_Lmt9_Over_Tcell2_32 : 16|8@1+ (1,-50) [-50|205] "℃"  PC
 SG_ S2P_Lmt9_Over_DTcell2_32 : 24|8@1+ (1,-50) [-50|205] "℃"  PC
 SG_ S2P_Lmt9_Over_Tcell3_32 : 32|8@1+ (1,-50) [-50|205] "℃"  PC
 SG_ S2P_Lmt9_Over_DTcell3_32 : 40|8@1+ (1,-50) [-50|205] "℃"  PC

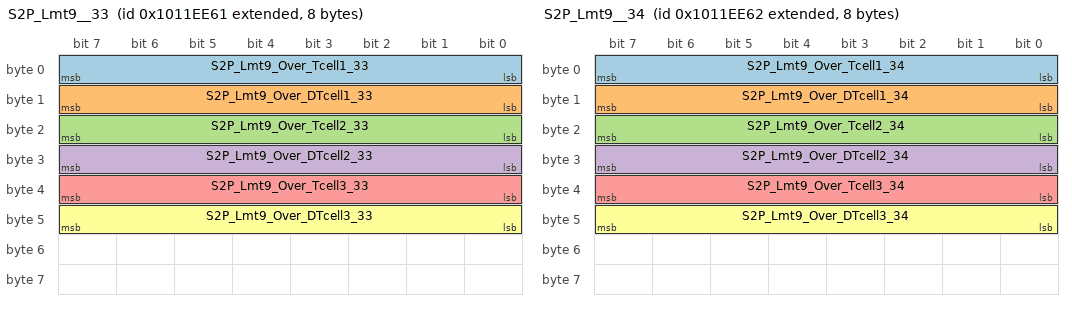
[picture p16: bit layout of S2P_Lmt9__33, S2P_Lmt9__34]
BO_ 2417094241 S2P_Lmt9__33: 8 SBMU
 SG_ S2P_Lmt9_Over_Tcell1_33 : 0|8@1+ (1,-50) [-50|205] "℃"  PC
 SG_ S2P_Lmt9_Over_DTcell1_33 : 8|8@1+ (1,-50) [-50|205] "℃"  PC
 SG_ S2P_Lmt9_Over_Tcell2_33 : 16|8@1+ (1,-50) [-50|205] "℃"  PC
 SG_ S2P_Lmt9_Over_DTcell2_33 : 24|8@1+ (1,-50) [-50|205] "℃"  PC
 SG_ S2P_Lmt9_Over_Tcell3_33 : 32|8@1+ (1,-50) [-50|205] "℃"  PC
 SG_ S2P_Lmt9_Over_DTcell3_33 : 40|8@1+ (1,-50) [-50|205] "℃"  PC

BO_ 2417094242 S2P_Lmt9__34: 8 SBMU
 SG_ S2P_Lmt9_Over_Tcell1_34 : 0|8@1+ (1,-50) [-50|205] "℃"  PC
 SG_ S2P_Lmt9_Over_DTcell1_34 : 8|8@1+ (1,-50) [-50|205] "℃"  PC
 SG_ S2P_Lmt9_Over_Tcell2_34 : 16|8@1+ (1,-50) [-50|205] "℃"  PC
 SG_ S2P_Lmt9_Over_DTcell2_34 : 24|8@1+ (1,-50) [-50|205] "℃"  PC
 SG_ S2P_Lmt9_Over_Tcell3_34 : 32|8@1+ (1,-50) [-50|205] "℃"  PC
 SG_ S2P_Lmt9_Over_DTcell3_34 : 40|8@1+ (1,-50) [-50|205] "℃"  PC

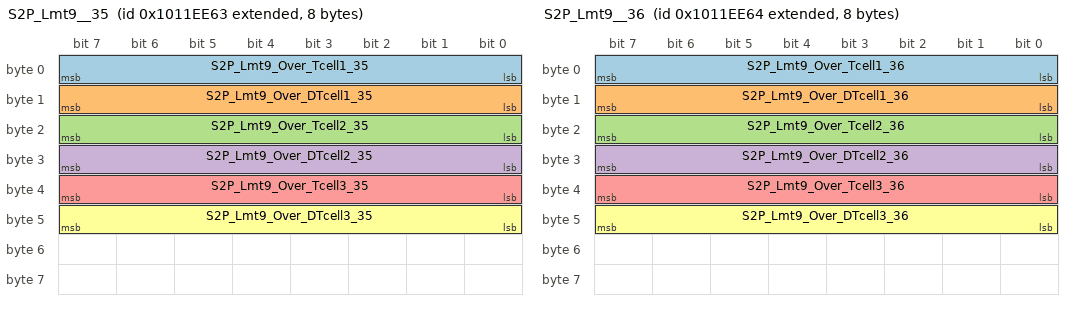
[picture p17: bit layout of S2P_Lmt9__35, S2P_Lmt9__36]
BO_ 2417094243 S2P_Lmt9__35: 8 SBMU
 SG_ S2P_Lmt9_Over_Tcell1_35 : 0|8@1+ (1,-50) [-50|205] "℃"  PC
 SG_ S2P_Lmt9_Over_DTcell1_35 : 8|8@1+ (1,-50) [-50|205] "℃"  PC
 SG_ S2P_Lmt9_Over_Tcell2_35 : 16|8@1+ (1,-50) [-50|205] "℃"  PC
 SG_ S2P_Lmt9_Over_DTcell2_35 : 24|8@1+ (1,-50) [-50|205] "℃"  PC
 SG_ S2P_Lmt9_Over_Tcell3_35 : 32|8@1+ (1,-50) [-50|205] "℃"  PC
 SG_ S2P_Lmt9_Over_DTcell3_35 : 40|8@1+ (1,-50) [-50|205] "℃"  PC

BO_ 2417094244 S2P_Lmt9__36: 8 SBMU
 SG_ S2P_Lmt9_Over_Tcell1_36 : 0|8@1+ (1,-50) [-50|205] "℃"  PC
 SG_ S2P_Lmt9_Over_DTcell1_36 : 8|8@1+ (1,-50) [-50|205] "℃"  PC
 SG_ S2P_Lmt9_Over_Tcell2_36 : 16|8@1+ (1,-50) [-50|205] "℃"  PC
 SG_ S2P_Lmt9_Over_DTcell2_36 : 24|8@1+ (1,-50) [-50|205] "℃"  PC
 SG_ S2P_Lmt9_Over_Tcell3_36 : 32|8@1+ (1,-50) [-50|205] "℃"  PC
 SG_ S2P_Lmt9_Over_DTcell3_36 : 40|8@1+ (1,-50) [-50|205] "℃"  PC

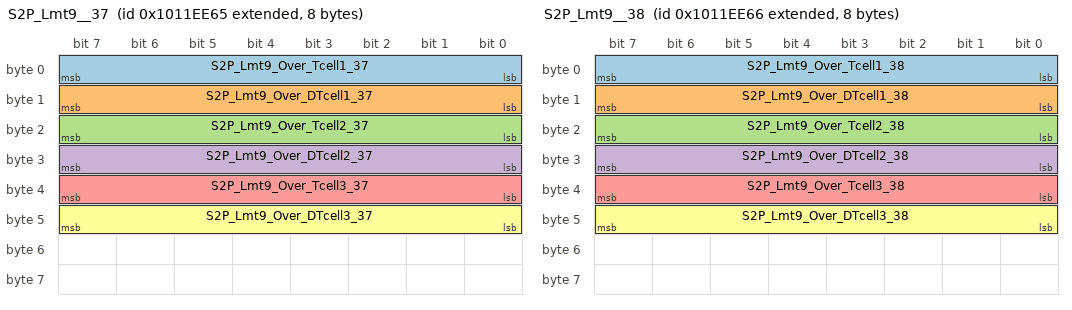
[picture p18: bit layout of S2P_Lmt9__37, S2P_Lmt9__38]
BO_ 2417094245 S2P_Lmt9__37: 8 SBMU
 SG_ S2P_Lmt9_Over_Tcell1_37 : 0|8@1+ (1,-50) [-50|205] "℃"  PC
 SG_ S2P_Lmt9_Over_DTcell1_37 : 8|8@1+ (1,-50) [-50|205] "℃"  PC
 SG_ S2P_Lmt9_Over_Tcell2_37 : 16|8@1+ (1,-50) [-50|205] "℃"  PC
 SG_ S2P_Lmt9_Over_DTcell2_37 : 24|8@1+ (1,-50) [-50|205] "℃"  PC
 SG_ S2P_Lmt9_Over_Tcell3_37 : 32|8@1+ (1,-50) [-50|205] "℃"  PC
 SG_ S2P_Lmt9_Over_DTcell3_37 : 40|8@1+ (1,-50) [-50|205] "℃"  PC

BO_ 2417094246 S2P_Lmt9__38: 8 SBMU
 SG_ S2P_Lmt9_Over_Tcell1_38 : 0|8@1+ (1,-50) [-50|205] "℃"  PC
 SG_ S2P_Lmt9_Over_DTcell1_38 : 8|8@1+ (1,-50) [-50|205] "℃"  PC
 SG_ S2P_Lmt9_Over_Tcell2_38 : 16|8@1+ (1,-50) [-50|205] "℃"  PC
 SG_ S2P_Lmt9_Over_DTcell2_38 : 24|8@1+ (1,-50) [-50|205] "℃"  PC
 SG_ S2P_Lmt9_Over_Tcell3_38 : 32|8@1+ (1,-50) [-50|205] "℃"  PC
 SG_ S2P_Lmt9_Over_DTcell3_38 : 40|8@1+ (1,-50) [-50|205] "℃"  PC

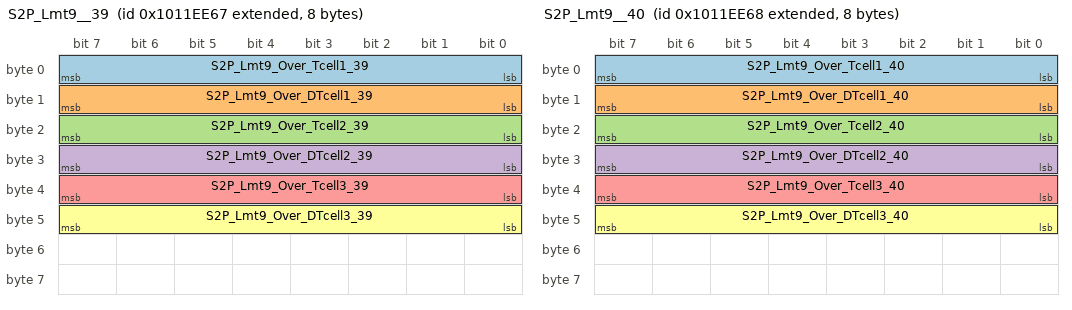
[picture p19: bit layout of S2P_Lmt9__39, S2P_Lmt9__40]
BO_ 2417094247 S2P_Lmt9__39: 8 SBMU
 SG_ S2P_Lmt9_Over_Tcell1_39 : 0|8@1+ (1,-50) [-50|205] "℃"  PC
 SG_ S2P_Lmt9_Over_DTcell1_39 : 8|8@1+ (1,-50) [-50|205] "℃"  PC
 SG_ S2P_Lmt9_Over_Tcell2_39 : 16|8@1+ (1,-50) [-50|205] "℃"  PC
 SG_ S2P_Lmt9_Over_DTcell2_39 : 24|8@1+ (1,-50) [-50|205] "℃"  PC
 SG_ S2P_Lmt9_Over_Tcell3_39 : 32|8@1+ (1,-50) [-50|205] "℃"  PC
 SG_ S2P_Lmt9_Over_DTcell3_39 : 40|8@1+ (1,-50) [-50|205] "℃"  PC

BO_ 2417094248 S2P_Lmt9__40: 8 SBMU
 SG_ S2P_Lmt9_Over_Tcell1_40 : 0|8@1+ (1,-50) [-50|205] "℃"  PC
 SG_ S2P_Lmt9_Over_DTcell1_40 : 8|8@1+ (1,-50) [-50|205] "℃"  PC
 SG_ S2P_Lmt9_Over_Tcell2_40 : 16|8@1+ (1,-50) [-50|205] "℃"  PC
 SG_ S2P_Lmt9_Over_DTcell2_40 : 24|8@1+ (1,-50) [-50|205] "℃"  PC
 SG_ S2P_Lmt9_Over_Tcell3_40 : 32|8@1+ (1,-50) [-50|205] "℃"  PC
 SG_ S2P_Lmt9_Over_DTcell3_40 : 40|8@1+ (1,-50) [-50|205] "℃"  PC

BO_ 2417094249 S2P_Lmt9__41: 8 SBMU
 SG_ S2P_Lmt9_Over_Tcell1_41 : 0|8@1+ (1,-50) [-50|205] "℃"  PC
 SG_ S2P_Lmt9_Over_DTcell1_41 : 8|8@1+ (1,-50) [-50|205] "℃"  PC
 SG_ S2P_Lmt9_Over_Tcell2_41 : 16|8@1+ (1,-50) [-50|205] "℃"  PC
 SG_ S2P_Lmt9_Over_DTcell2_41 : 24|8@1+ (1,-50) [-50|205] "℃"  PC
 SG_ S2P_Lmt9_Over_Tcell3_41 : 32|8@1+ (1,-50) [-50|205] "℃"  PC
 SG_ S2P_Lmt9_Over_DTcell3_41 : 40|8@1+ (1,-50) [-50|205] "℃"  PC

BO_ 2417094250 S2P_Lmt9__42: 8 SBMU
 SG_ S2P_Lmt9_Over_Tcell1_42 : 0|8@1+ (1,-50) [-50|205] "℃"  PC
 SG_ S2P_Lmt9_Over_DTcell1_42 : 8|8@1+ (1,-50) [-50|205] "℃"  PC
 SG_ S2P_Lmt9_Over_Tcell2_42 : 16|8@1+ (1,-50) [-50|205] "℃"  PC
 SG_ S2P_Lmt9_Over_DTcell2_42 : 24|8@1+ (1,-50) [-50|205] "℃"  PC
 SG_ S2P_Lmt9_Over_Tcell3_42 : 32|8@1+ (1,-50) [-50|205] "℃"  PC
 SG_ S2P_Lmt9_Over_DTcell3_42 : 40|8@1+ (1,-50) [-50|205] "℃"  PC

BO_ 2417094251 S2P_Lmt9__43: 8 SBMU
 SG_ S2P_Lmt9_Over_Tcell1_43 : 0|8@1+ (1,-50) [-50|205] "℃"  PC
 SG_ S2P_Lmt9_Over_DTcell1_43 : 8|8@1+ (1,-50) [-50|205] "℃"  PC
 SG_ S2P_Lmt9_Over_Tcell2_43 : 16|8@1+ (1,-50) [-50|205] "℃"  PC
 SG_ S2P_Lmt9_Over_DTcell2_43 : 24|8@1+ (1,-50) [-50|205] "℃"  PC
 SG_ S2P_Lmt9_Over_Tcell3_43 : 32|8@1+ (1,-50) [-50|205] "℃"  PC
 SG_ S2P_Lmt9_Over_DTcell3_43 : 40|8@1+ (1,-50) [-50|205] "℃"  PC

BO_ 2417094252 S2P_Lmt9__44: 8 SBMU
 SG_ S2P_Lmt9_Over_Tcell1_44 : 0|8@1+ (1,-50) [-50|205] "℃"  PC
 SG_ S2P_Lmt9_Over_DTcell1_44 : 8|8@1+ (1,-50) [-50|205] "℃"  PC
 SG_ S2P_Lmt9_Over_Tcell2_44 : 16|8@1+ (1,-50) [-50|205] "℃"  PC
 SG_ S2P_Lmt9_Over_DTcell2_44 : 24|8@1+ (1,-50) [-50|205] "℃"  PC
 SG_ S2P_Lmt9_Over_Tcell3_44 : 32|8@1+ (1,-50) [-50|205] "℃"  PC
 SG_ S2P_Lmt9_Over_DTcell3_44 : 40|8@1+ (1,-50) [-50|205] "℃"  PC

BO_ 2417094253 S2P_Lmt9__45: 8 SBMU
 SG_ S2P_Lmt9_Over_Tcell1_45 : 0|8@1+ (1,-50) [-50|205] "℃"  PC
 SG_ S2P_Lmt9_Over_DTcell1_45 : 8|8@1+ (1,-50) [-50|205] "℃"  PC
 SG_ S2P_Lmt9_Over_Tcell2_45 : 16|8@1+ (1,-50) [-50|205] "℃"  PC
 SG_ S2P_Lmt9_Over_DTcell2_45 : 24|8@1+ (1,-50) [-50|205] "℃"  PC
 SG_ S2P_Lmt9_Over_Tcell3_45 : 32|8@1+ (1,-50) [-50|205] "℃"  PC
 SG_ S2P_Lmt9_Over_DTcell3_45 : 40|8@1+ (1,-50) [-50|205] "℃"  PC

BO_ 2417094254 S2P_Lmt9__46: 8 SBMU
 SG_ S2P_Lmt9_Over_Tcell1_46 : 0|8@1+ (1,-50) [-50|205] "℃"  PC
 SG_ S2P_Lmt9_Over_DTcell1_46 : 8|8@1+ (1,-50) [-50|205] "℃"  PC
 SG_ S2P_Lmt9_Over_Tcell2_46 : 16|8@1+ (1,-50) [-50|205] "℃"  PC
 SG_ S2P_Lmt9_Over_DTcell2_46 : 24|8@1+ (1,-50) [-50|205] "℃"  PC
 SG_ S2P_Lmt9_Over_Tcell3_46 : 32|8@1+ (1,-50) [-50|205] "℃"  PC
 SG_ S2P_Lmt9_Over_DTcell3_46 : 40|8@1+ (1,-50) [-50|205] "℃"  PC

BO_ 2417094255 S2P_Lmt9__47: 8 SBMU
 SG_ S2P_Lmt9_Over_Tcell1_47 : 0|8@1+ (1,-50) [-50|205] "℃"  PC
 SG_ S2P_Lmt9_Over_DTcell1_47 : 8|8@1+ (1,-50) [-50|205] "℃"  PC
 SG_ S2P_Lmt9_Over_Tcell2_47 : 16|8@1+ (1,-50) [-50|205] "℃"  PC
 SG_ S2P_Lmt9_Over_DTcell2_47 : 24|8@1+ (1,-50) [-50|205] "℃"  PC
 SG_ S2P_Lmt9_Over_Tcell3_47 : 32|8@1+ (1,-50) [-50|205] "℃"  PC
 SG_ S2P_Lmt9_Over_DTcell3_47 : 40|8@1+ (1,-50) [-50|205] "℃"  PC

BO_ 2417094256 S2P_Lmt9__48: 8 SBMU
 SG_ S2P_Lmt9_Over_Tcell1_48 : 0|8@1+ (1,-50) [-50|205] "℃"  PC
 SG_ S2P_Lmt9_Over_DTcell1_48 : 8|8@1+ (1,-50) [-50|205] "℃"  PC
 SG_ S2P_Lmt9_Over_Tcell2_48 : 16|8@1+ (1,-50) [-50|205] "℃"  PC
 SG_ S2P_Lmt9_Over_DTcell2_48 : 24|8@1+ (1,-50) [-50|205] "℃"  PC
 SG_ S2P_Lmt9_Over_Tcell3_48 : 32|8@1+ (1,-50) [-50|205] "℃"  PC
 SG_ S2P_Lmt9_Over_DTcell3_48 : 40|8@1+ (1,-50) [-50|205] "℃"  PC

BO_ 2417094257 S2P_Lmt9__49: 8 SBMU
 SG_ S2P_Lmt9_Over_Tcell1_49 : 0|8@1+ (1,-50) [-50|205] "℃"  PC
 SG_ S2P_Lmt9_Over_DTcell1_49 : 8|8@1+ (1,-50) [-50|205] "℃"  PC
 SG_ S2P_Lmt9_Over_Tcell2_49 : 16|8@1+ (1,-50) [-50|205] "℃"  PC
 SG_ S2P_Lmt9_Over_DTcell2_49 : 24|8@1+ (1,-50) [-50|205] "℃"  PC
 SG_ S2P_Lmt9_Over_Tcell3_49 : 32|8@1+ (1,-50) [-50|205] "℃"  PC
 SG_ S2P_Lmt9_Over_DTcell3_49 : 40|8@1+ (1,-50) [-50|205] "℃"  PC

BO_ 2417094258 S2P_Lmt9__50: 8 SBMU
 SG_ S2P_Lmt9_Over_Tcell1_50 : 0|8@1+ (1,-50) [-50|205] "℃"  PC
 SG_ S2P_Lmt9_Over_DTcell1_50 : 8|8@1+ (1,-50) [-50|205] "℃"  PC
 SG_ S2P_Lmt9_Over_Tcell2_50 : 16|8@1+ (1,-50) [-50|205] "℃"  PC
 SG_ S2P_Lmt9_Over_DTcell2_50 : 24|8@1+ (1,-50) [-50|205] "℃"  PC
 SG_ S2P_Lmt9_Over_Tcell3_50 : 32|8@1+ (1,-50) [-50|205] "℃"  PC
 SG_ S2P_Lmt9_Over_DTcell3_50 : 40|8@1+ (1,-50) [-50|205] "℃"  PC

BO_ 2417094259 S2P_Lmt9__51: 8 SBMU
 SG_ S2P_Lmt9_Over_Tcell1_51 : 0|8@1+ (1,-50) [-50|205] "℃"  PC
 SG_ S2P_Lmt9_Over_DTcell1_51 : 8|8@1+ (1,-50) [-50|205] "℃"  PC
 SG_ S2P_Lmt9_Over_Tcell2_51 : 16|8@1+ (1,-50) [-50|205] "℃"  PC
 SG_ S2P_Lmt9_Over_DTcell2_51 : 24|8@1+ (1,-50) [-50|205] "℃"  PC
 SG_ S2P_Lmt9_Over_Tcell3_51 : 32|8@1+ (1,-50) [-50|205] "℃"  PC
 SG_ S2P_Lmt9_Over_DTcell3_51 : 40|8@1+ (1,-50) [-50|205] "℃"  PC

BO_ 2417094260 S2P_Lmt9__52: 8 SBMU
 SG_ S2P_Lmt9_Over_Tcell1_52 : 0|8@1+ (1,-50) [-50|205] "℃"  PC
 SG_ S2P_Lmt9_Over_DTcell1_52 : 8|8@1+ (1,-50) [-50|205] "℃"  PC
 SG_ S2P_Lmt9_Over_Tcell2_52 : 16|8@1+ (1,-50) [-50|205] "℃"  PC
 SG_ S2P_Lmt9_Over_DTcell2_52 : 24|8@1+ (1,-50) [-50|205] "℃"  PC
 SG_ S2P_Lmt9_Over_Tcell3_52 : 32|8@1+ (1,-50) [-50|205] "℃"  PC
 SG_ S2P_Lmt9_Over_DTcell3_52 : 40|8@1+ (1,-50) [-50|205] "℃"  PC

BO_ 2417094261 S2P_Lmt9__53: 8 SBMU
 SG_ S2P_Lmt9_Over_Tcell1_53 : 0|8@1+ (1,-50) [-50|205] "℃"  PC
 SG_ S2P_Lmt9_Over_DTcell1_53 : 8|8@1+ (1,-50) [-50|205] "℃"  PC
 SG_ S2P_Lmt9_Over_Tcell2_53 : 16|8@1+ (1,-50) [-50|205] "℃"  PC
 SG_ S2P_Lmt9_Over_DTcell2_53 : 24|8@1+ (1,-50) [-50|205] "℃"  PC
 SG_ S2P_Lmt9_Over_Tcell3_53 : 32|8@1+ (1,-50) [-50|205] "℃"  PC
 SG_ S2P_Lmt9_Over_DTcell3_53 : 40|8@1+ (1,-50) [-50|205] "℃"  PC

BO_ 2417094262 S2P_Lmt9__54: 8 SBMU
 SG_ S2P_Lmt9_Over_Tcell1_54 : 0|8@1+ (1,-50) [-50|205] "℃"  PC
 SG_ S2P_Lmt9_Over_DTcell1_54 : 8|8@1+ (1,-50) [-50|205] "℃"  PC
 SG_ S2P_Lmt9_Over_Tcell2_54 : 16|8@1+ (1,-50) [-50|205] "℃"  PC
 SG_ S2P_Lmt9_Over_DTcell2_54 : 24|8@1+ (1,-50) [-50|205] "℃"  PC
 SG_ S2P_Lmt9_Over_Tcell3_54 : 32|8@1+ (1,-50) [-50|205] "℃"  PC
 SG_ S2P_Lmt9_Over_DTcell3_54 : 40|8@1+ (1,-50) [-50|205] "℃"  PC

BO_ 2417094263 S2P_Lmt9__55: 8 SBMU
 SG_ S2P_Lmt9_Over_Tcell1_55 : 0|8@1+ (1,-50) [-50|205] "℃"  PC
 SG_ S2P_Lmt9_Over_DTcell1_55 : 8|8@1+ (1,-50) [-50|205] "℃"  PC
 SG_ S2P_Lmt9_Over_Tcell2_55 : 16|8@1+ (1,-50) [-50|205] "℃"  PC
 SG_ S2P_Lmt9_Over_DTcell2_55 : 24|8@1+ (1,-50) [-50|205] "℃"  PC
 SG_ S2P_Lmt9_Over_Tcell3_55 : 32|8@1+ (1,-50) [-50|205] "℃"  PC
 SG_ S2P_Lmt9_Over_DTcell3_55 : 40|8@1+ (1,-50) [-50|205] "℃"  PC

BO_ 2417094264 S2P_Lmt9__56: 8 SBMU
 SG_ S2P_Lmt9_Over_Tcell1_56 : 0|8@1+ (1,-50) [-50|205] "℃"  PC
 SG_ S2P_Lmt9_Over_DTcell1_56 : 8|8@1+ (1,-50) [-50|205] "℃"  PC
 SG_ S2P_Lmt9_Over_Tcell2_56 : 16|8@1+ (1,-50) [-50|205] "℃"  PC
 SG_ S2P_Lmt9_Over_DTcell2_56 : 24|8@1+ (1,-50) [-50|205] "℃"  PC
 SG_ S2P_Lmt9_Over_Tcell3_56 : 32|8@1+ (1,-50) [-50|205] "℃"  PC
 SG_ S2P_Lmt9_Over_DTcell3_56 : 40|8@1+ (1,-50) [-50|205] "℃"  PC

BO_ 2417094265 S2P_Lmt9__57: 8 SBMU
 SG_ S2P_Lmt9_Over_Tcell1_57 : 0|8@1+ (1,-50) [-50|205] "℃"  PC
 SG_ S2P_Lmt9_Over_DTcell1_57 : 8|8@1+ (1,-50) [-50|205] "℃"  PC
 SG_ S2P_Lmt9_Over_Tcell2_57 : 16|8@1+ (1,-50) [-50|205] "℃"  PC
 SG_ S2P_Lmt9_Over_DTcell2_57 : 24|8@1+ (1,-50) [-50|205] "℃"  PC
 SG_ S2P_Lmt9_Over_Tcell3_57 : 32|8@1+ (1,-50) [-50|205] "℃"  PC
 SG_ S2P_Lmt9_Over_DTcell3_57 : 40|8@1+ (1,-50) [-50|205] "℃"  PC

BO_ 2417094266 S2P_Lmt9__58: 8 SBMU
 SG_ S2P_Lmt9_Over_Tcell1_58 : 0|8@1+ (1,-50) [-50|205] "℃"  PC
 SG_ S2P_Lmt9_Over_DTcell1_58 : 8|8@1+ (1,-50) [-50|205] "℃"  PC
 SG_ S2P_Lmt9_Over_Tcell2_58 : 16|8@1+ (1,-50) [-50|205] "℃"  PC
 SG_ S2P_Lmt9_Over_DTcell2_58 : 24|8@1+ (1,-50) [-50|205] "℃"  PC
 SG_ S2P_Lmt9_Over_Tcell3_58 : 32|8@1+ (1,-50) [-50|205] "℃"  PC
 SG_ S2P_Lmt9_Over_DTcell3_58 : 40|8@1+ (1,-50) [-50|205] "℃"  PC

BO_ 2417094267 S2P_Lmt9__59: 8 SBMU
 SG_ S2P_Lmt9_Over_Tcell1_59 : 0|8@1+ (1,-50) [-50|205] "℃"  PC
 SG_ S2P_Lmt9_Over_DTcell1_59 : 8|8@1+ (1,-50) [-50|205] "℃"  PC
 SG_ S2P_Lmt9_Over_Tcell2_59 : 16|8@1+ (1,-50) [-50|205] "℃"  PC
 SG_ S2P_Lmt9_Over_DTcell2_59 : 24|8@1+ (1,-50) [-50|205] "℃"  PC
 SG_ S2P_Lmt9_Over_Tcell3_59 : 32|8@1+ (1,-50) [-50|205] "℃"  PC
 SG_ S2P_Lmt9_Over_DTcell3_59 : 40|8@1+ (1,-50) [-50|205] "℃"  PC

BO_ 2417094268 S2P_Lmt9__60: 8 SBMU
 SG_ S2P_Lmt9_Over_Tcell1_60 : 0|8@1+ (1,-50) [-50|205] "℃"  PC
 SG_ S2P_Lmt9_Over_DTcell1_60 : 8|8@1+ (1,-50) [-50|205] "℃"  PC
 SG_ S2P_Lmt9_Over_Tcell2_60 : 16|8@1+ (1,-50) [-50|205] "℃"  PC
 SG_ S2P_Lmt9_Over_DTcell2_60 : 24|8@1+ (1,-50) [-50|205] "℃"  PC
 SG_ S2P_Lmt9_Over_Tcell3_60 : 32|8@1+ (1,-50) [-50|205] "℃"  PC
 SG_ S2P_Lmt9_Over_DTcell3_60 : 40|8@1+ (1,-50) [-50|205] "℃"  PC

BO_ 2417094269 S2P_Lmt9__61: 8 SBMU
 SG_ S2P_Lmt9_Over_Tcell1_61 : 0|8@1+ (1,-50) [-50|205] "℃"  PC
 SG_ S2P_Lmt9_Over_DTcell1_61 : 8|8@1+ (1,-50) [-50|205] "℃"  PC
 SG_ S2P_Lmt9_Over_Tcell2_61 : 16|8@1+ (1,-50) [-50|205] "℃"  PC
 SG_ S2P_Lmt9_Over_DTcell2_61 : 24|8@1+ (1,-50) [-50|205] "℃"  PC
 SG_ S2P_Lmt9_Over_Tcell3_61 : 32|8@1+ (1,-50) [-50|205] "℃"  PC
 SG_ S2P_Lmt9_Over_DTcell3_61 : 40|8@1+ (1,-50) [-50|205] "℃"  PC

BO_ 2417094270 S2P_Lmt9__62: 8 SBMU
 SG_ S2P_Lmt9_Over_Tcell1_62 : 0|8@1+ (1,-50) [-50|205] "℃"  PC
 SG_ S2P_Lmt9_Over_DTcell1_62 : 8|8@1+ (1,-50) [-50|205] "℃"  PC
 SG_ S2P_Lmt9_Over_Tcell2_62 : 16|8@1+ (1,-50) [-50|205] "℃"  PC
 SG_ S2P_Lmt9_Over_DTcell2_62 : 24|8@1+ (1,-50) [-50|205] "℃"  PC
 SG_ S2P_Lmt9_Over_Tcell3_62 : 32|8@1+ (1,-50) [-50|205] "℃"  PC
 SG_ S2P_Lmt9_Over_DTcell3_62 : 40|8@1+ (1,-50) [-50|205] "℃"  PC

BO_ 2417094271 S2P_Lmt9__63: 8 SBMU
 SG_ S2P_Lmt9_Over_Tcell1_63 : 0|8@1+ (1,-50) [-50|205] "℃"  PC
 SG_ S2P_Lmt9_Over_DTcell1_63 : 8|8@1+ (1,-50) [-50|205] "℃"  PC
 SG_ S2P_Lmt9_Over_Tcell2_63 : 16|8@1+ (1,-50) [-50|205] "℃"  PC
 SG_ S2P_Lmt9_Over_DTcell2_63 : 24|8@1+ (1,-50) [-50|205] "℃"  PC
 SG_ S2P_Lmt9_Over_Tcell3_63 : 32|8@1+ (1,-50) [-50|205] "℃"  PC
 SG_ S2P_Lmt9_Over_DTcell3_63 : 40|8@1+ (1,-50) [-50|205] "℃"  PC

BO_ 2417159745 S2P_Lmt10__01: 8 SBMU
 SG_ S2P_Lmt10_Under_Tcell1_01 : 0|8@1+ (1,-50) [-50|205] "℃"  PC
 SG_ S2P_Lmt10_Under_DTcell1_01 : 8|8@1+ (1,-50) [-50|205] "℃"  PC
 SG_ S2P_Lmt10_Under_Tcell2_01 : 16|8@1+ (1,-50) [-50|205] "℃"  PC
 SG_ S2P_Lmt10_Under_DTcell2_01 : 24|8@1+ (1,-50) [-50|205] "℃"  PC
 SG_ S2P_Lmt10_Under_Tcell3_01 : 32|8@1+ (1,-50) [-50|205] "℃"  PC
 SG_ S2P_Lmt10_Under_DTcell3_01 : 40|8@1+ (1,-50) [-50|205] "℃"  PC

BO_ 2417159746 S2P_Lmt10__02: 8 SBMU
 SG_ S2P_Lmt10_Under_Tcell1_02 : 0|8@1+ (1,-50) [-50|205] "℃"  PC
 SG_ S2P_Lmt10_Under_DTcell1_02 : 8|8@1+ (1,-50) [-50|205] "℃"  PC
 SG_ S2P_Lmt10_Under_Tcell2_02 : 16|8@1+ (1,-50) [-50|205] "℃"  PC
 SG_ S2P_Lmt10_Under_DTcell2_02 : 24|8@1+ (1,-50) [-50|205] "℃"  PC
 SG_ S2P_Lmt10_Under_Tcell3_02 : 32|8@1+ (1,-50) [-50|205] "℃"  PC
 SG_ S2P_Lmt10_Under_DTcell3_02 : 40|8@1+ (1,-50) [-50|205] "℃"  PC

BO_ 2417159747 S2P_Lmt10__03: 8 SBMU
 SG_ S2P_Lmt10_Under_Tcell1_03 : 0|8@1+ (1,-50) [-50|205] "℃"  PC
 SG_ S2P_Lmt10_Under_DTcell1_03 : 8|8@1+ (1,-50) [-50|205] "℃"  PC
 SG_ S2P_Lmt10_Under_Tcell2_03 : 16|8@1+ (1,-50) [-50|205] "℃"  PC
 SG_ S2P_Lmt10_Under_DTcell2_03 : 24|8@1+ (1,-50) [-50|205] "℃"  PC
 SG_ S2P_Lmt10_Under_Tcell3_03 : 32|8@1+ (1,-50) [-50|205] "℃"  PC
 SG_ S2P_Lmt10_Under_DTcell3_03 : 40|8@1+ (1,-50) [-50|205] "℃"  PC

BO_ 2417159748 S2P_Lmt10__04: 8 SBMU
 SG_ S2P_Lmt10_Under_Tcell1_04 : 0|8@1+ (1,-50) [-50|205] "℃"  PC
 SG_ S2P_Lmt10_Under_DTcell1_04 : 8|8@1+ (1,-50) [-50|205] "℃"  PC
 SG_ S2P_Lmt10_Under_Tcell2_04 : 16|8@1+ (1,-50) [-50|205] "℃"  PC
 SG_ S2P_Lmt10_Under_DTcell2_04 : 24|8@1+ (1,-50) [-50|205] "℃"  PC
 SG_ S2P_Lmt10_Under_Tcell3_04 : 32|8@1+ (1,-50) [-50|205] "℃"  PC
 SG_ S2P_Lmt10_Under_DTcell3_04 : 40|8@1+ (1,-50) [-50|205] "℃"  PC

BO_ 2417159749 S2P_Lmt10__05: 8 SBMU
 SG_ S2P_Lmt10_Under_Tcell1_05 : 0|8@1+ (1,-50) [-50|205] "℃"  PC
 SG_ S2P_Lmt10_Under_DTcell1_05 : 8|8@1+ (1,-50) [-50|205] "℃"  PC
 SG_ S2P_Lmt10_Under_Tcell2_05 : 16|8@1+ (1,-50) [-50|205] "℃"  PC
 SG_ S2P_Lmt10_Under_DTcell2_05 : 24|8@1+ (1,-50) [-50|205] "℃"  PC
 SG_ S2P_Lmt10_Under_Tcell3_05 : 32|8@1+ (1,-50) [-50|205] "℃"  PC
 SG_ S2P_Lmt10_Under_DTcell3_05 : 40|8@1+ (1,-50) [-50|205] "℃"  PC

BO_ 2417159750 S2P_Lmt10__06: 8 SBMU
 SG_ S2P_Lmt10_Under_Tcell1_06 : 0|8@1+ (1,-50) [-50|205] "℃"  PC
 SG_ S2P_Lmt10_Under_DTcell1_06 : 8|8@1+ (1,-50) [-50|205] "℃"  PC
 SG_ S2P_Lmt10_Under_Tcell2_06 : 16|8@1+ (1,-50) [-50|205] "℃"  PC
 SG_ S2P_Lmt10_Under_DTcell2_06 : 24|8@1+ (1,-50) [-50|205] "℃"  PC
 SG_ S2P_Lmt10_Under_Tcell3_06 : 32|8@1+ (1,-50) [-50|205] "℃"  PC
 SG_ S2P_Lmt10_Under_DTcell3_06 : 40|8@1+ (1,-50) [-50|205] "℃"  PC

BO_ 2417159751 S2P_Lmt10__07: 8 SBMU
 SG_ S2P_Lmt10_Under_Tcell1_07 : 0|8@1+ (1,-50) [-50|205] "℃"  PC
 SG_ S2P_Lmt10_Under_DTcell1_07 : 8|8@1+ (1,-50) [-50|205] "℃"  PC
 SG_ S2P_Lmt10_Under_Tcell2_07 : 16|8@1+ (1,-50) [-50|205] "℃"  PC
 SG_ S2P_Lmt10_Under_DTcell2_07 : 24|8@1+ (1,-50) [-50|205] "℃"  PC
 SG_ S2P_Lmt10_Under_Tcell3_07 : 32|8@1+ (1,-50) [-50|205] "℃"  PC
 SG_ S2P_Lmt10_Under_DTcell3_07 : 40|8@1+ (1,-50) [-50|205] "℃"  PC

BO_ 2417159752 S2P_Lmt10__08: 8 SBMU
 SG_ S2P_Lmt10_Under_Tcell1_08 : 0|8@1+ (1,-50) [-50|205] "℃"  PC
 SG_ S2P_Lmt10_Under_DTcell1_08 : 8|8@1+ (1,-50) [-50|205] "℃"  PC
 SG_ S2P_Lmt10_Under_Tcell2_08 : 16|8@1+ (1,-50) [-50|205] "℃"  PC
 SG_ S2P_Lmt10_Under_DTcell2_08 : 24|8@1+ (1,-50) [-50|205] "℃"  PC
 SG_ S2P_Lmt10_Under_Tcell3_08 : 32|8@1+ (1,-50) [-50|205] "℃"  PC
 SG_ S2P_Lmt10_Under_DTcell3_08 : 40|8@1+ (1,-50) [-50|205] "℃"  PC

BO_ 2417159753 S2P_Lmt10__09: 8 SBMU
 SG_ S2P_Lmt10_Under_Tcell1_09 : 0|8@1+ (1,-50) [-50|205] "℃"  PC
 SG_ S2P_Lmt10_Under_DTcell1_09 : 8|8@1+ (1,-50) [-50|205] "℃"  PC
 SG_ S2P_Lmt10_Under_Tcell2_09 : 16|8@1+ (1,-50) [-50|205] "℃"  PC
 SG_ S2P_Lmt10_Under_DTcell2_09 : 24|8@1+ (1,-50) [-50|205] "℃"  PC
 SG_ S2P_Lmt10_Under_Tcell3_09 : 32|8@1+ (1,-50) [-50|205] "℃"  PC
 SG_ S2P_Lmt10_Under_DTcell3_09 : 40|8@1+ (1,-50) [-50|205] "℃"  PC

BO_ 2417159754 S2P_Lmt10__10: 8 SBMU
 SG_ S2P_Lmt10_Under_Tcell1_10 : 0|8@1+ (1,-50) [-50|205] "℃"  PC
 SG_ S2P_Lmt10_Under_DTcell1_10 : 8|8@1+ (1,-50) [-50|205] "℃"  PC
 SG_ S2P_Lmt10_Under_Tcell2_10 : 16|8@1+ (1,-50) [-50|205] "℃"  PC
 SG_ S2P_Lmt10_Under_DTcell2_10 : 24|8@1+ (1,-50) [-50|205] "℃"  PC
 SG_ S2P_Lmt10_Under_Tcell3_10 : 32|8@1+ (1,-50) [-50|205] "℃"  PC
 SG_ S2P_Lmt10_Under_DTcell3_10 : 40|8@1+ (1,-50) [-50|205] "℃"  PC

BO_ 2417159755 S2P_Lmt10__11: 8 SBMU
 SG_ S2P_Lmt10_Under_Tcell1_11 : 0|8@1+ (1,-50) [-50|205] "℃"  PC
 SG_ S2P_Lmt10_Under_DTcell1_11 : 8|8@1+ (1,-50) [-50|205] "℃"  PC
 SG_ S2P_Lmt10_Under_Tcell2_11 : 16|8@1+ (1,-50) [-50|205] "℃"  PC
 SG_ S2P_Lmt10_Under_DTcell2_11 : 24|8@1+ (1,-50) [-50|205] "℃"  PC
 SG_ S2P_Lmt10_Under_Tcell3_11 : 32|8@1+ (1,-50) [-50|205] "℃"  PC
 SG_ S2P_Lmt10_Under_DTcell3_11 : 40|8@1+ (1,-50) [-50|205] "℃"  PC

BO_ 2417159756 S2P_Lmt10__12: 8 SBMU
 SG_ S2P_Lmt10_Under_Tcell1_12 : 0|8@1+ (1,-50) [-50|205] "℃"  PC
 SG_ S2P_Lmt10_Under_DTcell1_12 : 8|8@1+ (1,-50) [-50|205] "℃"  PC
 SG_ S2P_Lmt10_Under_Tcell2_12 : 16|8@1+ (1,-50) [-50|205] "℃"  PC
 SG_ S2P_Lmt10_Under_DTcell2_12 : 24|8@1+ (1,-50) [-50|205] "℃"  PC
 SG_ S2P_Lmt10_Under_Tcell3_12 : 32|8@1+ (1,-50) [-50|205] "℃"  PC
 SG_ S2P_Lmt10_Under_DTcell3_12 : 40|8@1+ (1,-50) [-50|205] "℃"  PC

BO_ 2417159757 S2P_Lmt10__13: 8 SBMU
 SG_ S2P_Lmt10_Under_Tcell1_13 : 0|8@1+ (1,-50) [-50|205] "℃"  PC
 SG_ S2P_Lmt10_Under_DTcell1_13 : 8|8@1+ (1,-50) [-50|205] "℃"  PC
 SG_ S2P_Lmt10_Under_Tcell2_13 : 16|8@1+ (1,-50) [-50|205] "℃"  PC
 SG_ S2P_Lmt10_Under_DTcell2_13 : 24|8@1+ (1,-50) [-50|205] "℃"  PC
 SG_ S2P_Lmt10_Under_Tcell3_13 : 32|8@1+ (1,-50) [-50|205] "℃"  PC
 SG_ S2P_Lmt10_Under_DTcell3_13 : 40|8@1+ (1,-50) [-50|205] "℃"  PC

BO_ 2417159758 S2P_Lmt10__14: 8 SBMU
 SG_ S2P_Lmt10_Under_Tcell1_14 : 0|8@1+ (1,-50) [-50|205] "℃"  PC
 SG_ S2P_Lmt10_Under_DTcell1_14 : 8|8@1+ (1,-50) [-50|205] "℃"  PC
 SG_ S2P_Lmt10_Under_Tcell2_14 : 16|8@1+ (1,-50) [-50|205] "℃"  PC
 SG_ S2P_Lmt10_Under_DTcell2_14 : 24|8@1+ (1,-50) [-50|205] "℃"  PC
 SG_ S2P_Lmt10_Under_Tcell3_14 : 32|8@1+ (1,-50) [-50|205] "℃"  PC
 SG_ S2P_Lmt10_Under_DTcell3_14 : 40|8@1+ (1,-50) [-50|205] "℃"  PC

BO_ 2417159759 S2P_Lmt10__15: 8 SBMU
 SG_ S2P_Lmt10_Under_Tcell1_15 : 0|8@1+ (1,-50) [-50|205] "℃"  PC
 SG_ S2P_Lmt10_Under_DTcell1_15 : 8|8@1+ (1,-50) [-50|205] "℃"  PC
 SG_ S2P_Lmt10_Under_Tcell2_15 : 16|8@1+ (1,-50) [-50|205] "℃"  PC
 SG_ S2P_Lmt10_Under_DTcell2_15 : 24|8@1+ (1,-50) [-50|205] "℃"  PC
 SG_ S2P_Lmt10_Under_Tcell3_15 : 32|8@1+ (1,-50) [-50|205] "℃"  PC
 SG_ S2P_Lmt10_Under_DTcell3_15 : 40|8@1+ (1,-50) [-50|205] "℃"  PC

BO_ 2417159760 S2P_Lmt10__16: 8 SBMU
 SG_ S2P_Lmt10_Under_Tcell1_16 : 0|8@1+ (1,-50) [-50|205] "℃"  PC
 SG_ S2P_Lmt10_Under_DTcell1_16 : 8|8@1+ (1,-50) [-50|205] "℃"  PC
 SG_ S2P_Lmt10_Under_Tcell2_16 : 16|8@1+ (1,-50) [-50|205] "℃"  PC
 SG_ S2P_Lmt10_Under_DTcell2_16 : 24|8@1+ (1,-50) [-50|205] "℃"  PC
 SG_ S2P_Lmt10_Under_Tcell3_16 : 32|8@1+ (1,-50) [-50|205] "℃"  PC
 SG_ S2P_Lmt10_Under_DTcell3_16 : 40|8@1+ (1,-50) [-50|205] "℃"  PC

BO_ 2417159761 S2P_Lmt10__17: 8 SBMU
 SG_ S2P_Lmt10_Under_Tcell1_17 : 0|8@1+ (1,-50) [-50|205] "℃"  PC
 SG_ S2P_Lmt10_Under_DTcell1_17 : 8|8@1+ (1,-50) [-50|205] "℃"  PC
 SG_ S2P_Lmt10_Under_Tcell2_17 : 16|8@1+ (1,-50) [-50|205] "℃"  PC
 SG_ S2P_Lmt10_Under_DTcell2_17 : 24|8@1+ (1,-50) [-50|205] "℃"  PC
 SG_ S2P_Lmt10_Under_Tcell3_17 : 32|8@1+ (1,-50) [-50|205] "℃"  PC
 SG_ S2P_Lmt10_Under_DTcell3_17 : 40|8@1+ (1,-50) [-50|205] "℃"  PC

BO_ 2417159762 S2P_Lmt10__18: 8 SBMU
 SG_ S2P_Lmt10_Under_Tcell1_18 : 0|8@1+ (1,-50) [-50|205] "℃"  PC
 SG_ S2P_Lmt10_Under_DTcell1_18 : 8|8@1+ (1,-50) [-50|205] "℃"  PC
 SG_ S2P_Lmt10_Under_Tcell2_18 : 16|8@1+ (1,-50) [-50|205] "℃"  PC
 SG_ S2P_Lmt10_Under_DTcell2_18 : 24|8@1+ (1,-50) [-50|205] "℃"  PC
 SG_ S2P_Lmt10_Under_Tcell3_18 : 32|8@1+ (1,-50) [-50|205] "℃"  PC
 SG_ S2P_Lmt10_Under_DTcell3_18 : 40|8@1+ (1,-50) [-50|205] "℃"  PC

BO_ 2417159763 S2P_Lmt10__19: 8 SBMU
 SG_ S2P_Lmt10_Under_Tcell1_19 : 0|8@1+ (1,-50) [-50|205] "℃"  PC
 SG_ S2P_Lmt10_Under_DTcell1_19 : 8|8@1+ (1,-50) [-50|205] "℃"  PC
 SG_ S2P_Lmt10_Under_Tcell2_19 : 16|8@1+ (1,-50) [-50|205] "℃"  PC
 SG_ S2P_Lmt10_Under_DTcell2_19 : 24|8@1+ (1,-50) [-50|205] "℃"  PC
 SG_ S2P_Lmt10_Under_Tcell3_19 : 32|8@1+ (1,-50) [-50|205] "℃"  PC
 SG_ S2P_Lmt10_Under_DTcell3_19 : 40|8@1+ (1,-50) [-50|205] "℃"  PC

BO_ 2417159764 S2P_Lmt10__20: 8 SBMU
 SG_ S2P_Lmt10_Under_Tcell1_20 : 0|8@1+ (1,-50) [-50|205] "℃"  PC
 SG_ S2P_Lmt10_Under_DTcell1_20 : 8|8@1+ (1,-50) [-50|205] "℃"  PC
 SG_ S2P_Lmt10_Under_Tcell2_20 : 16|8@1+ (1,-50) [-50|205] "℃"  PC
 SG_ S2P_Lmt10_Under_DTcell2_20 : 24|8@1+ (1,-50) [-50|205] "℃"  PC
 SG_ S2P_Lmt10_Under_Tcell3_20 : 32|8@1+ (1,-50) [-50|205] "℃"  PC
 SG_ S2P_Lmt10_Under_DTcell3_20 : 40|8@1+ (1,-50) [-50|205] "℃"  PC

BO_ 2417159765 S2P_Lmt10__21: 8 SBMU
 SG_ S2P_Lmt10_Under_Tcell1_21 : 0|8@1+ (1,-50) [-50|205] "℃"  PC
 SG_ S2P_Lmt10_Under_DTcell1_21 : 8|8@1+ (1,-50) [-50|205] "℃"  PC
 SG_ S2P_Lmt10_Under_Tcell2_21 : 16|8@1+ (1,-50) [-50|205] "℃"  PC
 SG_ S2P_Lmt10_Under_DTcell2_21 : 24|8@1+ (1,-50) [-50|205] "℃"  PC
 SG_ S2P_Lmt10_Under_Tcell3_21 : 32|8@1+ (1,-50) [-50|205] "℃"  PC
 SG_ S2P_Lmt10_Under_DTcell3_21 : 40|8@1+ (1,-50) [-50|205] "℃"  PC

BO_ 2417159766 S2P_Lmt10__22: 8 SBMU
 SG_ S2P_Lmt10_Under_Tcell1_22 : 0|8@1+ (1,-50) [-50|205] "℃"  PC
 SG_ S2P_Lmt10_Under_DTcell1_22 : 8|8@1+ (1,-50) [-50|205] "℃"  PC
 SG_ S2P_Lmt10_Under_Tcell2_22 : 16|8@1+ (1,-50) [-50|205] "℃"  PC
 SG_ S2P_Lmt10_Under_DTcell2_22 : 24|8@1+ (1,-50) [-50|205] "℃"  PC
 SG_ S2P_Lmt10_Under_Tcell3_22 : 32|8@1+ (1,-50) [-50|205] "℃"  PC
 SG_ S2P_Lmt10_Under_DTcell3_22 : 40|8@1+ (1,-50) [-50|205] "℃"  PC

BO_ 2417159767 S2P_Lmt10__23: 8 SBMU
 SG_ S2P_Lmt10_Under_Tcell1_23 : 0|8@1+ (1,-50) [-50|205] "℃"  PC
 SG_ S2P_Lmt10_Under_DTcell1_23 : 8|8@1+ (1,-50) [-50|205] "℃"  PC
 SG_ S2P_Lmt10_Under_Tcell2_23 : 16|8@1+ (1,-50) [-50|205] "℃"  PC
 SG_ S2P_Lmt10_Under_DTcell2_23 : 24|8@1+ (1,-50) [-50|205] "℃"  PC
 SG_ S2P_Lmt10_Under_Tcell3_23 : 32|8@1+ (1,-50) [-50|205] "℃"  PC
 SG_ S2P_Lmt10_Under_DTcell3_23 : 40|8@1+ (1,-50) [-50|205] "℃"  PC

BO_ 2417159768 S2P_Lmt10__24: 8 SBMU
 SG_ S2P_Lmt10_Under_Tcell1_24 : 0|8@1+ (1,-50) [-50|205] "℃"  PC
 SG_ S2P_Lmt10_Under_DTcell1_24 : 8|8@1+ (1,-50) [-50|205] "℃"  PC
 SG_ S2P_Lmt10_Under_Tcell2_24 : 16|8@1+ (1,-50) [-50|205] "℃"  PC
 SG_ S2P_Lmt10_Under_DTcell2_24 : 24|8@1+ (1,-50) [-50|205] "℃"  PC
 SG_ S2P_Lmt10_Under_Tcell3_24 : 32|8@1+ (1,-50) [-50|205] "℃"  PC
 SG_ S2P_Lmt10_Under_DTcell3_24 : 40|8@1+ (1,-50) [-50|205] "℃"  PC

BO_ 2417159769 S2P_Lmt10__25: 8 SBMU
 SG_ S2P_Lmt10_Under_Tcell1_25 : 0|8@1+ (1,-50) [-50|205] "℃"  PC
 SG_ S2P_Lmt10_Under_DTcell1_25 : 8|8@1+ (1,-50) [-50|205] "℃"  PC
 SG_ S2P_Lmt10_Under_Tcell2_25 : 16|8@1+ (1,-50) [-50|205] "℃"  PC
 SG_ S2P_Lmt10_Under_DTcell2_25 : 24|8@1+ (1,-50) [-50|205] "℃"  PC
 SG_ S2P_Lmt10_Under_Tcell3_25 : 32|8@1+ (1,-50) [-50|205] "℃"  PC
 SG_ S2P_Lmt10_Under_DTcell3_25 : 40|8@1+ (1,-50) [-50|205] "℃"  PC

BO_ 2417159770 S2P_Lmt10__26: 8 SBMU
 SG_ S2P_Lmt10_Under_Tcell1_26 : 0|8@1+ (1,-50) [-50|205] "℃"  PC
 SG_ S2P_Lmt10_Under_DTcell1_26 : 8|8@1+ (1,-50) [-50|205] "℃"  PC
 SG_ S2P_Lmt10_Under_Tcell2_26 : 16|8@1+ (1,-50) [-50|205] "℃"  PC
 SG_ S2P_Lmt10_Under_DTcell2_26 : 24|8@1+ (1,-50) [-50|205] "℃"  PC
 SG_ S2P_Lmt10_Under_Tcell3_26 : 32|8@1+ (1,-50) [-50|205] "℃"  PC
 SG_ S2P_Lmt10_Under_DTcell3_26 : 40|8@1+ (1,-50) [-50|205] "℃"  PC

BO_ 2417159771 S2P_Lmt10__27: 8 SBMU
 SG_ S2P_Lmt10_Under_Tcell1_27 : 0|8@1+ (1,-50) [-50|205] "℃"  PC
 SG_ S2P_Lmt10_Under_DTcell1_27 : 8|8@1+ (1,-50) [-50|205] "℃"  PC
 SG_ S2P_Lmt10_Under_Tcell2_27 : 16|8@1+ (1,-50) [-50|205] "℃"  PC
 SG_ S2P_Lmt10_Under_DTcell2_27 : 24|8@1+ (1,-50) [-50|205] "℃"  PC
 SG_ S2P_Lmt10_Under_Tcell3_27 : 32|8@1+ (1,-50) [-50|205] "℃"  PC
 SG_ S2P_Lmt10_Under_DTcell3_27 : 40|8@1+ (1,-50) [-50|205] "℃"  PC

BO_ 2417159772 S2P_Lmt10__28: 8 SBMU
 SG_ S2P_Lmt10_Under_Tcell1_28 : 0|8@1+ (1,-50) [-50|205] "℃"  PC
 SG_ S2P_Lmt10_Under_DTcell1_28 : 8|8@1+ (1,-50) [-50|205] "℃"  PC
 SG_ S2P_Lmt10_Under_Tcell2_28 : 16|8@1+ (1,-50) [-50|205] "℃"  PC
 SG_ S2P_Lmt10_Under_DTcell2_28 : 24|8@1+ (1,-50) [-50|205] "℃"  PC
 SG_ S2P_Lmt10_Under_Tcell3_28 : 32|8@1+ (1,-50) [-50|205] "℃"  PC
 SG_ S2P_Lmt10_Under_DTcell3_28 : 40|8@1+ (1,-50) [-50|205] "℃"  PC

BO_ 2417159773 S2P_Lmt10__29: 8 SBMU
 SG_ S2P_Lmt10_Under_Tcell1_29 : 0|8@1+ (1,-50) [-50|205] "℃"  PC
 SG_ S2P_Lmt10_Under_DTcell1_29 : 8|8@1+ (1,-50) [-50|205] "℃"  PC
 SG_ S2P_Lmt10_Under_Tcell2_29 : 16|8@1+ (1,-50) [-50|205] "℃"  PC
 SG_ S2P_Lmt10_Under_DTcell2_29 : 24|8@1+ (1,-50) [-50|205] "℃"  PC
 SG_ S2P_Lmt10_Under_Tcell3_29 : 32|8@1+ (1,-50) [-50|205] "℃"  PC
 SG_ S2P_Lmt10_Under_DTcell3_29 : 40|8@1+ (1,-50) [-50|205] "℃"  PC

BO_ 2417159774 S2P_Lmt10__30: 8 SBMU
 SG_ S2P_Lmt10_Under_Tcell1_30 : 0|8@1+ (1,-50) [-50|205] "℃"  PC
 SG_ S2P_Lmt10_Under_DTcell1_30 : 8|8@1+ (1,-50) [-50|205] "℃"  PC
 SG_ S2P_Lmt10_Under_Tcell2_30 : 16|8@1+ (1,-50) [-50|205] "℃"  PC
 SG_ S2P_Lmt10_Under_DTcell2_30 : 24|8@1+ (1,-50) [-50|205] "℃"  PC
 SG_ S2P_Lmt10_Under_Tcell3_30 : 32|8@1+ (1,-50) [-50|205] "℃"  PC
 SG_ S2P_Lmt10_Under_DTcell3_30 : 40|8@1+ (1,-50) [-50|205] "℃"  PC

BO_ 2417159775 S2P_Lmt10__31: 8 SBMU
 SG_ S2P_Lmt10_Under_Tcell1_31 : 0|8@1+ (1,-50) [-50|205] "℃"  PC
 SG_ S2P_Lmt10_Under_DTcell1_31 : 8|8@1+ (1,-50) [-50|205] "℃"  PC
 SG_ S2P_Lmt10_Under_Tcell2_31 : 16|8@1+ (1,-50) [-50|205] "℃"  PC
 SG_ S2P_Lmt10_Under_DTcell2_31 : 24|8@1+ (1,-50) [-50|205] "℃"  PC
 SG_ S2P_Lmt10_Under_Tcell3_31 : 32|8@1+ (1,-50) [-50|205] "℃"  PC
 SG_ S2P_Lmt10_Under_DTcell3_31 : 40|8@1+ (1,-50) [-50|205] "℃"  PC

BO_ 2417159776 S2P_Lmt10__32: 8 SBMU
 SG_ S2P_Lmt10_Under_Tcell1_32 : 0|8@1+ (1,-50) [-50|205] "℃"  PC
 SG_ S2P_Lmt10_Under_DTcell1_32 : 8|8@1+ (1,-50) [-50|205] "℃"  PC
 SG_ S2P_Lmt10_Under_Tcell2_32 : 16|8@1+ (1,-50) [-50|205] "℃"  PC
 SG_ S2P_Lmt10_Under_DTcell2_32 : 24|8@1+ (1,-50) [-50|205] "℃"  PC
 SG_ S2P_Lmt10_Under_Tcell3_32 : 32|8@1+ (1,-50) [-50|205] "℃"  PC
 SG_ S2P_Lmt10_Under_DTcell3_32 : 40|8@1+ (1,-50) [-50|205] "℃"  PC

BO_ 2417159777 S2P_Lmt10__33: 8 SBMU
 SG_ S2P_Lmt10_Under_Tcell1_33 : 0|8@1+ (1,-50) [-50|205] "℃"  PC
 SG_ S2P_Lmt10_Under_DTcell1_33 : 8|8@1+ (1,-50) [-50|205] "℃"  PC
 SG_ S2P_Lmt10_Under_Tcell2_33 : 16|8@1+ (1,-50) [-50|205] "℃"  PC
 SG_ S2P_Lmt10_Under_DTcell2_33 : 24|8@1+ (1,-50) [-50|205] "℃"  PC
 SG_ S2P_Lmt10_Under_Tcell3_33 : 32|8@1+ (1,-50) [-50|205] "℃"  PC
 SG_ S2P_Lmt10_Under_DTcell3_33 : 40|8@1+ (1,-50) [-50|205] "℃"  PC

BO_ 2417159778 S2P_Lmt10__34: 8 SBMU
 SG_ S2P_Lmt10_Under_Tcell1_34 : 0|8@1+ (1,-50) [-50|205] "℃"  PC
 SG_ S2P_Lmt10_Under_DTcell1_34 : 8|8@1+ (1,-50) [-50|205] "℃"  PC
 SG_ S2P_Lmt10_Under_Tcell2_34 : 16|8@1+ (1,-50) [-50|205] "℃"  PC
 SG_ S2P_Lmt10_Under_DTcell2_34 : 24|8@1+ (1,-50) [-50|205] "℃"  PC
 SG_ S2P_Lmt10_Under_Tcell3_34 : 32|8@1+ (1,-50) [-50|205] "℃"  PC
 SG_ S2P_Lmt10_Under_DTcell3_34 : 40|8@1+ (1,-50) [-50|205] "℃"  PC

BO_ 2417159779 S2P_Lmt10__35: 8 SBMU
 SG_ S2P_Lmt10_Under_Tcell1_35 : 0|8@1+ (1,-50) [-50|205] "℃"  PC
 SG_ S2P_Lmt10_Under_DTcell1_35 : 8|8@1+ (1,-50) [-50|205] "℃"  PC
 SG_ S2P_Lmt10_Under_Tcell2_35 : 16|8@1+ (1,-50) [-50|205] "℃"  PC
 SG_ S2P_Lmt10_Under_DTcell2_35 : 24|8@1+ (1,-50) [-50|205] "℃"  PC
 SG_ S2P_Lmt10_Under_Tcell3_35 : 32|8@1+ (1,-50) [-50|205] "℃"  PC
 SG_ S2P_Lmt10_Under_DTcell3_35 : 40|8@1+ (1,-50) [-50|205] "℃"  PC

BO_ 2417159780 S2P_Lmt10__36: 8 SBMU
 SG_ S2P_Lmt10_Under_Tcell1_36 : 0|8@1+ (1,-50) [-50|205] "℃"  PC
 SG_ S2P_Lmt10_Under_DTcell1_36 : 8|8@1+ (1,-50) [-50|205] "℃"  PC
 SG_ S2P_Lmt10_Under_Tcell2_36 : 16|8@1+ (1,-50) [-50|205] "℃"  PC
 SG_ S2P_Lmt10_Under_DTcell2_36 : 24|8@1+ (1,-50) [-50|205] "℃"  PC
 SG_ S2P_Lmt10_Under_Tcell3_36 : 32|8@1+ (1,-50) [-50|205] "℃"  PC
 SG_ S2P_Lmt10_Under_DTcell3_36 : 40|8@1+ (1,-50) [-50|205] "℃"  PC

BO_ 2417159781 S2P_Lmt10__37: 8 SBMU
 SG_ S2P_Lmt10_Under_Tcell1_37 : 0|8@1+ (1,-50) [-50|205] "℃"  PC
 SG_ S2P_Lmt10_Under_DTcell1_37 : 8|8@1+ (1,-50) [-50|205] "℃"  PC
 SG_ S2P_Lmt10_Under_Tcell2_37 : 16|8@1+ (1,-50) [-50|205] "℃"  PC
 SG_ S2P_Lmt10_Under_DTcell2_37 : 24|8@1+ (1,-50) [-50|205] "℃"  PC
 SG_ S2P_Lmt10_Under_Tcell3_37 : 32|8@1+ (1,-50) [-50|205] "℃"  PC
 SG_ S2P_Lmt10_Under_DTcell3_37 : 40|8@1+ (1,-50) [-50|205] "℃"  PC

BO_ 2417159782 S2P_Lmt10__38: 8 SBMU
 SG_ S2P_Lmt10_Under_Tcell1_38 : 0|8@1+ (1,-50) [-50|205] "℃"  PC
 SG_ S2P_Lmt10_Under_DTcell1_38 : 8|8@1+ (1,-50) [-50|205] "℃"  PC
 SG_ S2P_Lmt10_Under_Tcell2_38 : 16|8@1+ (1,-50) [-50|205] "℃"  PC
 SG_ S2P_Lmt10_Under_DTcell2_38 : 24|8@1+ (1,-50) [-50|205] "℃"  PC
 SG_ S2P_Lmt10_Under_Tcell3_38 : 32|8@1+ (1,-50) [-50|205] "℃"  PC
 SG_ S2P_Lmt10_Under_DTcell3_38 : 40|8@1+ (1,-50) [-50|205] "℃"  PC

BO_ 2417159783 S2P_Lmt10__39: 8 SBMU
 SG_ S2P_Lmt10_Under_Tcell1_39 : 0|8@1+ (1,-50) [-50|205] "℃"  PC
 SG_ S2P_Lmt10_Under_DTcell1_39 : 8|8@1+ (1,-50) [-50|205] "℃"  PC
 SG_ S2P_Lmt10_Under_Tcell2_39 : 16|8@1+ (1,-50) [-50|205] "℃"  PC
 SG_ S2P_Lmt10_Under_DTcell2_39 : 24|8@1+ (1,-50) [-50|205] "℃"  PC
 SG_ S2P_Lmt10_Under_Tcell3_39 : 32|8@1+ (1,-50) [-50|205] "℃"  PC
 SG_ S2P_Lmt10_Under_DTcell3_39 : 40|8@1+ (1,-50) [-50|205] "℃"  PC

CM_ SG_ 2416897608 S2P_Lmt6_Under_Utank1_08 "电池簇放电电压一级报警值";
CM_ SG_ 2416897608 S2P_Lmt6_Under_Utank2_08 "电池簇放电电压二级报警值";
CM_ SG_ 2416897608 S2P_Lmt6_Under_Utank3_08 "电池簇放电电压三级报警值";
CM_ SG_ 2416897608 S2P_Lmt6_Under_DUtank_08 "分柜欠压告警消除回差阈值";
CM_ SG_ 2416897609 S2P_Lmt6_Under_Utank1_09 "电池簇放电电压一级报警值";
CM_ SG_ 2416897609 S2P_Lmt6_Under_Utank2_09 "电池簇放电电压二级报警值";
CM_ SG_ 2416897609 S2P_Lmt6_Under_Utank3_09 "电池簇放电电压三级报警值";
CM_ SG_ 2416897609 S2P_Lmt6_Under_DUtank_09 "分柜欠压告警消除回差阈值";
CM_ SG_ 2416897610 S2P_Lmt6_Under_Utank1_10 "电池簇放电电压一级报警值";
CM_ SG_ 2416897610 S2P_Lmt6_Under_Utank2_10 "电池簇放电电压二级报警值";
CM_ SG_ 2416897610 S2P_Lmt6_Under_Utank3_10 "电池簇放电电压三级报警值";
CM_ SG_ 2416897610 S2P_Lmt6_Under_DUtank_10 "分柜欠压告警消除回差阈值";
CM_ SG_ 2416897611 S2P_Lmt6_Under_Utank1_11 "电池簇放电电压一级报警值";
CM_ SG_ 2416897611 S2P_Lmt6_Under_Utank2_11 "电池簇放电电压二级报警值";
CM_ SG_ 2416897611 S2P_Lmt6_Under_Utank3_11 "电池簇放电电压三级报警值";
CM_ SG_ 2416897611 S2P_Lmt6_Under_DUtank_11 "分柜欠压告警消除回差阈值";
CM_ SG_ 2416897612 S2P_Lmt6_Under_Utank1_12 "电池簇放电电压一级报警值";
CM_ SG_ 2416897612 S2P_Lmt6_Under_Utank2_12 "电池簇放电电压二级报警值";
CM_ SG_ 2416897612 S2P_Lmt6_Under_Utank3_12 "电池簇放电电压三级报警值";
CM_ SG_ 2416897612 S2P_Lmt6_Under_DUtank_12 "分柜欠压告警消除回差阈值";
CM_ SG_ 2416897613 S2P_Lmt6_Under_Utank1_13 "电池簇放电电压一级报警值";
CM_ SG_ 2416897613 S2P_Lmt6_Under_Utank2_13 "电池簇放电电压二级报警值";
CM_ SG_ 2416897613 S2P_Lmt6_Under_Utank3_13 "电池簇放电电压三级报警值";
CM_ SG_ 2416897613 S2P_Lmt6_Under_DUtank_13 "分柜欠压告警消除回差阈值";
CM_ SG_ 2416897614 S2P_Lmt6_Under_Utank1_14 "电池簇放电电压一级报警值";
CM_ SG_ 2416897614 S2P_Lmt6_Under_Utank2_14 "电池簇放电电压二级报警值";
CM_ SG_ 2416897614 S2P_Lmt6_Under_Utank3_14 "电池簇放电电压三级报警值";
CM_ SG_ 2416897614 S2P_Lmt6_Under_DUtank_14 "分柜欠压告警消除回差阈值";
CM_ SG_ 2416897615 S2P_Lmt6_Under_Utank1_15 "电池簇放电电压一级报警值";
CM_ SG_ 2416897615 S2P_Lmt6_Under_Utank2_15 "电池簇放电电压二级报警值";
CM_ SG_ 2416897615 S2P_Lmt6_Under_Utank3_15 "电池簇放电电压三级报警值";
CM_ SG_ 2416897615 S2P_Lmt6_Under_DUtank_15 "分柜欠压告警消除回差阈值";
CM_ SG_ 2416897616 S2P_Lmt6_Under_Utank1_16 "电池簇放电电压一级报警值";
CM_ SG_ 2416897616 S2P_Lmt6_Under_Utank2_16 "电池簇放电电压二级报警值";
CM_ SG_ 2416897616 S2P_Lmt6_Under_Utank3_16 "电池簇放电电压三级报警值";
CM_ SG_ 2416897616 S2P_Lmt6_Under_DUtank_16 "分柜欠压告警消除回差阈值";
CM_ SG_ 2416897617 S2P_Lmt6_Under_Utank1_17 "电池簇放电电压一级报警值";
CM_ SG_ 2416897617 S2P_Lmt6_Under_Utank2_17 "电池簇放电电压二级报警值";
CM_ SG_ 2416897617 S2P_Lmt6_Under_Utank3_17 "电池簇放电电压三级报警值";
CM_ SG_ 2416897617 S2P_Lmt6_Under_DUtank_17 "分柜欠压告警消除回差阈值";
CM_ SG_ 2416897618 S2P_Lmt6_Under_Utank1_18 "电池簇放电电压一级报警值";
CM_ SG_ 2416897618 S2P_Lmt6_Under_Utank2_18 "电池簇放电电压二级报警值";
CM_ SG_ 2416897618 S2P_Lmt6_Under_Utank3_18 "电池簇放电电压三级报警值";
CM_ SG_ 2416897618 S2P_Lmt6_Under_DUtank_18 "分柜欠压告警消除回差阈值";
CM_ SG_ 2416897619 S2P_Lmt6_Under_Utank1_19 "电池簇放电电压一级报警值";
CM_ SG_ 2416897619 S2P_Lmt6_Under_Utank2_19 "电池簇放电电压二级报警值";
CM_ SG_ 2416897619 S2P_Lmt6_Under_Utank3_19 "电池簇放电电压三级报警值";
CM_ SG_ 2416897619 S2P_Lmt6_Under_DUtank_19 "分柜欠压告警消除回差阈值";
CM_ SG_ 2416897620 S2P_Lmt6_Under_Utank1_20 "电池簇放电电压一级报警值";
CM_ SG_ 2416897620 S2P_Lmt6_Under_Utank2_20 "电池簇放电电压二级报警值";
CM_ SG_ 2416897620 S2P_Lmt6_Under_Utank3_20 "电池簇放电电压三级报警值";
CM_ SG_ 2416897620 S2P_Lmt6_Under_DUtank_20 "分柜欠压告警消除回差阈值";
CM_ SG_ 2416897621 S2P_Lmt6_Under_Utank1_21 "电池簇放电电压一级报警值";
CM_ SG_ 2416897621 S2P_Lmt6_Under_Utank2_21 "电池簇放电电压二级报警值";
CM_ SG_ 2416897621 S2P_Lmt6_Under_Utank3_21 "电池簇放电电压三级报警值";
CM_ SG_ 2416897621 S2P_Lmt6_Under_DUtank_21 "分柜欠压告警消除回差阈值";
CM_ SG_ 2416897622 S2P_Lmt6_Under_Utank1_22 "电池簇放电电压一级报警值";
CM_ SG_ 2416897622 S2P_Lmt6_Under_Utank2_22 "电池簇放电电压二级报警值";
CM_ SG_ 2416897622 S2P_Lmt6_Under_Utank3_22 "电池簇放电电压三级报警值";
CM_ SG_ 2416897622 S2P_Lmt6_Under_DUtank_22 "分柜欠压告警消除回差阈值";
CM_ SG_ 2416897623 S2P_Lmt6_Under_Utank1_23 "电池簇放电电压一级报警值";
CM_ SG_ 2416897623 S2P_Lmt6_Under_Utank2_23 "电池簇放电电压二级报警值";
CM_ SG_ 2416897623 S2P_Lmt6_Under_Utank3_23 "电池簇放电电压三级报警值";
CM_ SG_ 2416897623 S2P_Lmt6_Under_DUtank_23 "分柜欠压告警消除回差阈值";
CM_ SG_ 2416897624 S2P_Lmt6_Under_Utank1_24 "电池簇放电电压一级报警值";
CM_ SG_ 2416897624 S2P_Lmt6_Under_Utank2_24 "电池簇放电电压二级报警值";
CM_ SG_ 2416897624 S2P_Lmt6_Under_Utank3_24 "电池簇放电电压三级报警值";
CM_ SG_ 2416897624 S2P_Lmt6_Under_DUtank_24 "分柜欠压告警消除回差阈值";
CM_ SG_ 2416897625 S2P_Lmt6_Under_Utank1_25 "电池簇放电电压一级报警值";
CM_ SG_ 2416897625 S2P_Lmt6_Under_Utank2_25 "电池簇放电电压二级报警值";
CM_ SG_ 2416897625 S2P_Lmt6_Under_Utank3_25 "电池簇放电电压三级报警值";
CM_ SG_ 2416897625 S2P_Lmt6_Under_DUtank_25 "分柜欠压告警消除回差阈值";
CM_ SG_ 2416897626 S2P_Lmt6_Under_Utank1_26 "电池簇放电电压一级报警值";
CM_ SG_ 2416897626 S2P_Lmt6_Under_Utank2_26 "电池簇放电电压二级报警值";
CM_ SG_ 2416897626 S2P_Lmt6_Under_Utank3_26 "电池簇放电电压三级报警值";
CM_ SG_ 2416897626 S2P_Lmt6_Under_DUtank_26 "分柜欠压告警消除回差阈值";
CM_ SG_ 2416897627 S2P_Lmt6_Under_Utank1_27 "电池簇放电电压一级报警值";
CM_ SG_ 2416897627 S2P_Lmt6_Under_Utank2_27 "电池簇放电电压二级报警值";
CM_ SG_ 2416897627 S2P_Lmt6_Under_Utank3_27 "电池簇放电电压三级报警值";
CM_ SG_ 2416897627 S2P_Lmt6_Under_DUtank_27 "分柜欠压告警消除回差阈值";
CM_ SG_ 2416897628 S2P_Lmt6_Under_Utank1_28 "电池簇放电电压一级报警值";
CM_ SG_ 2416897628 S2P_Lmt6_Under_Utank2_28 "电池簇放电电压二级报警值";
CM_ SG_ 2416897628 S2P_Lmt6_Under_Utank3_28 "电池簇放电电压三级报警值";
CM_ SG_ 2416897628 S2P_Lmt6_Under_DUtank_28 "分柜欠压告警消除回差阈值";
CM_ SG_ 2416897629 S2P_Lmt6_Under_Utank1_29 "电池簇放电电压一级报警值";
CM_ SG_ 2416897629 S2P_Lmt6_Under_Utank2_29 "电池簇放电电压二级报警值";
CM_ SG_ 2416897629 S2P_Lmt6_Under_Utank3_29 "电池簇放电电压三级报警值";
CM_ SG_ 2416897629 S2P_Lmt6_Under_DUtank_29 "分柜欠压告警消除回差阈值";
CM_ SG_ 2416897630 S2P_Lmt6_Under_Utank1_30 "电池簇放电电压一级报警值";
CM_ SG_ 2416897630 S2P_Lmt6_Under_Utank2_30 "电池簇放电电压二级报警值";
CM_ SG_ 2416897630 S2P_Lmt6_Under_Utank3_30 "电池簇放电电压三级报警值";
CM_ SG_ 2416897630 S2P_Lmt6_Under_DUtank_30 "分柜欠压告警消除回差阈值";
CM_ SG_ 2416897631 S2P_Lmt6_Under_Utank1_31 "电池簇放电电压一级报警值";
CM_ SG_ 2416897631 S2P_Lmt6_Under_Utank2_31 "电池簇放电电压二级报警值";
CM_ SG_ 2416897631 S2P_Lmt6_Under_Utank3_31 "电池簇放电电压三级报警值";
CM_ SG_ 2416897631 S2P_Lmt6_Under_DUtank_31 "分柜欠压告警消除回差阈值";
CM_ SG_ 2416897632 S2P_Lmt6_Under_Utank1_32 "电池簇放电电压一级报警值";
CM_ SG_ 2416897632 S2P_Lmt6_Under_Utank2_32 "电池簇放电电压二级报警值";
CM_ SG_ 2416897632 S2P_Lmt6_Under_Utank3_32 "电池簇放电电压三级报警值";
CM_ SG_ 2416897632 S2P_Lmt6_Under_DUtank_32 "分柜欠压告警消除回差阈值";
CM_ SG_ 2416897633 S2P_Lmt6_Under_Utank1_33 "电池簇放电电压一级报警值";
CM_ SG_ 2416897633 S2P_Lmt6_Under_Utank2_33 "电池簇放电电压二级报警值";
CM_ SG_ 2416897633 S2P_Lmt6_Under_Utank3_33 "电池簇放电电压三级报警值";
CM_ SG_ 2416897633 S2P_Lmt6_Under_DUtank_33 "分柜欠压告警消除回差阈值";
CM_ SG_ 2416897634 S2P_Lmt6_Under_Utank1_34 "电池簇放电电压一级报警值";
CM_ SG_ 2416897634 S2P_Lmt6_Under_Utank2_34 "电池簇放电电压二级报警值";
CM_ SG_ 2416897634 S2P_Lmt6_Under_Utank3_34 "电池簇放电电压三级报警值";
CM_ SG_ 2416897634 S2P_Lmt6_Under_DUtank_34 "分柜欠压告警消除回差阈值";
CM_ SG_ 2416897635 S2P_Lmt6_Under_Utank1_35 "电池簇放电电压一级报警值";
CM_ SG_ 2416897635 S2P_Lmt6_Under_Utank2_35 "电池簇放电电压二级报警值";
CM_ SG_ 2416897635 S2P_Lmt6_Under_Utank3_35 "电池簇放电电压三级报警值";
CM_ SG_ 2416897635 S2P_Lmt6_Under_DUtank_35 "分柜欠压告警消除回差阈值";
CM_ SG_ 2416897636 S2P_Lmt6_Under_Utank1_36 "电池簇放电电压一级报警值";
CM_ SG_ 2416897636 S2P_Lmt6_Under_Utank2_36 "电池簇放电电压二级报警值";
CM_ SG_ 2416897636 S2P_Lmt6_Under_Utank3_36 "电池簇放电电压三级报警值";
CM_ SG_ 2416897636 S2P_Lmt6_Under_DUtank_36 "分柜欠压告警消除回差阈值";
CM_ SG_ 2416897637 S2P_Lmt6_Under_Utank1_37 "电池簇放电电压一级报警值";
CM_ SG_ 2416897637 S2P_Lmt6_Under_Utank2_37 "电池簇放电电压二级报警值";
CM_ SG_ 2416897637 S2P_Lmt6_Under_Utank3_37 "电池簇放电电压三级报警值";
CM_ SG_ 2416897637 S2P_Lmt6_Under_DUtank_37 "分柜欠压告警消除回差阈值";
CM_ SG_ 2416897638 S2P_Lmt6_Under_Utank1_38 "电池簇放电电压一级报警值";
CM_ SG_ 2416897638 S2P_Lmt6_Under_Utank2_38 "电池簇放电电压二级报警值";
CM_ SG_ 2416897638 S2P_Lmt6_Under_Utank3_38 "电池簇放电电压三级报警值";
CM_ SG_ 2416897638 S2P_Lmt6_Under_DUtank_38 "分柜欠压告警消除回差阈值";
CM_ SG_ 2416897639 S2P_Lmt6_Under_Utank1_39 "电池簇放电电压一级报警值";
CM_ SG_ 2416897639 S2P_Lmt6_Under_Utank2_39 "电池簇放电电压二级报警值";
CM_ SG_ 2416897639 S2P_Lmt6_Under_Utank3_39 "电池簇放电电压三级报警值";
CM_ SG_ 2416897639 S2P_Lmt6_Under_DUtank_39 "分柜欠压告警消除回差阈值";
CM_ SG_ 2416897640 S2P_Lmt6_Under_Utank1_40 "电池簇放电电压一级报警值";
CM_ SG_ 2416897640 S2P_Lmt6_Under_Utank2_40 "电池簇放电电压二级报警值";
CM_ SG_ 2416897640 S2P_Lmt6_Under_Utank3_40 "电池簇放电电压三级报警值";
CM_ SG_ 2416897640 S2P_Lmt6_Under_DUtank_40 "分柜欠压告警消除回差阈值";
CM_ SG_ 2416897641 S2P_Lmt6_Under_Utank1_41 "电池簇放电电压一级报警值";
CM_ SG_ 2416897641 S2P_Lmt6_Under_Utank2_41 "电池簇放电电压二级报警值";
CM_ SG_ 2416897641 S2P_Lmt6_Under_Utank3_41 "电池簇放电电压三级报警值";
CM_ SG_ 2416897641 S2P_Lmt6_Under_DUtank_41 "分柜欠压告警消除回差阈值";
CM_ SG_ 2416897642 S2P_Lmt6_Under_Utank1_42 "电池簇放电电压一级报警值";
CM_ SG_ 2416897642 S2P_Lmt6_Under_Utank2_42 "电池簇放电电压二级报警值";
CM_ SG_ 2416897642 S2P_Lmt6_Under_Utank3_42 "电池簇放电电压三级报警值";
CM_ SG_ 2416897642 S2P_Lmt6_Under_DUtank_42 "分柜欠压告警消除回差阈值";
CM_ SG_ 2416897643 S2P_Lmt6_Under_Utank1_43 "电池簇放电电压一级报警值";
CM_ SG_ 2416897643 S2P_Lmt6_Under_Utank2_43 "电池簇放电电压二级报警值";
CM_ SG_ 2416897643 S2P_Lmt6_Under_Utank3_43 "电池簇放电电压三级报警值";
CM_ SG_ 2416897643 S2P_Lmt6_Under_DUtank_43 "分柜欠压告警消除回差阈值";
CM_ SG_ 2416897644 S2P_Lmt6_Under_Utank1_44 "电池簇放电电压一级报警值";
CM_ SG_ 2416897644 S2P_Lmt6_Under_Utank2_44 "电池簇放电电压二级报警值";
CM_ SG_ 2416897644 S2P_Lmt6_Under_Utank3_44 "电池簇放电电压三级报警值";
CM_ SG_ 2416897644 S2P_Lmt6_Under_DUtank_44 "分柜欠压告警消除回差阈值";
CM_ SG_ 2416897645 S2P_Lmt6_Under_Utank1_45 "电池簇放电电压一级报警值";
CM_ SG_ 2416897645 S2P_Lmt6_Under_Utank2_45 "电池簇放电电压二级报警值";
CM_ SG_ 2416897645 S2P_Lmt6_Under_Utank3_45 "电池簇放电电压三级报警值";
CM_ SG_ 2416897645 S2P_Lmt6_Under_DUtank_45 "分柜欠压告警消除回差阈值";
CM_ SG_ 2416897646 S2P_Lmt6_Under_Utank1_46 "电池簇放电电压一级报警值";
CM_ SG_ 2416897646 S2P_Lmt6_Under_Utank2_46 "电池簇放电电压二级报警值";
CM_ SG_ 2416897646 S2P_Lmt6_Under_Utank3_46 "电池簇放电电压三级报警值";
CM_ SG_ 2416897646 S2P_Lmt6_Under_DUtank_46 "分柜欠压告警消除回差阈值";
CM_ SG_ 2416897647 S2P_Lmt6_Under_Utank1_47 "电池簇放电电压一级报警值";
CM_ SG_ 2416897647 S2P_Lmt6_Under_Utank2_47 "电池簇放电电压二级报警值";
CM_ SG_ 2416897647 S2P_Lmt6_Under_Utank3_47 "电池簇放电电压三级报警值";
CM_ SG_ 2416897647 S2P_Lmt6_Under_DUtank_47 "分柜欠压告警消除回差阈值";
CM_ SG_ 2416897648 S2P_Lmt6_Under_Utank1_48 "电池簇放电电压一级报警值";
CM_ SG_ 2416897648 S2P_Lmt6_Under_Utank2_48 "电池簇放电电压二级报警值";
CM_ SG_ 2416897648 S2P_Lmt6_Under_Utank3_48 "电池簇放电电压三级报警值";
CM_ SG_ 2416897648 S2P_Lmt6_Under_DUtank_48 "分柜欠压告警消除回差阈值";
CM_ SG_ 2416897649 S2P_Lmt6_Under_Utank1_49 "电池簇放电电压一级报警值";
CM_ SG_ 2416897649 S2P_Lmt6_Under_Utank2_49 "电池簇放电电压二级报警值";
CM_ SG_ 2416897649 S2P_Lmt6_Under_Utank3_49 "电池簇放电电压三级报警值";
CM_ SG_ 2416897649 S2P_Lmt6_Under_DUtank_49 "分柜欠压告警消除回差阈值";
CM_ SG_ 2416897650 S2P_Lmt6_Under_Utank1_50 "电池簇放电电压一级报警值";
CM_ SG_ 2416897650 S2P_Lmt6_Under_Utank2_50 "电池簇放电电压二级报警值";
CM_ SG_ 2416897650 S2P_Lmt6_Under_Utank3_50 "电池簇放电电压三级报警值";
CM_ SG_ 2416897650 S2P_Lmt6_Under_DUtank_50 "分柜欠压告警消除回差阈值";
CM_ SG_ 2416897651 S2P_Lmt6_Under_Utank1_51 "电池簇放电电压一级报警值";
CM_ SG_ 2416897651 S2P_Lmt6_Under_Utank2_51 "电池簇放电电压二级报警值";
CM_ SG_ 2416897651 S2P_Lmt6_Under_Utank3_51 "电池簇放电电压三级报警值";
CM_ SG_ 2416897651 S2P_Lmt6_Under_DUtank_51 "分柜欠压告警消除回差阈值";
CM_ SG_ 2416897652 S2P_Lmt6_Under_Utank1_52 "电池簇放电电压一级报警值";
CM_ SG_ 2416897652 S2P_Lmt6_Under_Utank2_52 "电池簇放电电压二级报警值";
CM_ SG_ 2416897652 S2P_Lmt6_Under_Utank3_52 "电池簇放电电压三级报警值";
CM_ SG_ 2416897652 S2P_Lmt6_Under_DUtank_52 "分柜欠压告警消除回差阈值";
CM_ SG_ 2416897653 S2P_Lmt6_Under_Utank1_53 "电池簇放电电压一级报警值";
CM_ SG_ 2416897653 S2P_Lmt6_Under_Utank2_53 "电池簇放电电压二级报警值";
CM_ SG_ 2416897653 S2P_Lmt6_Under_Utank3_53 "电池簇放电电压三级报警值";
CM_ SG_ 2416897653 S2P_Lmt6_Under_DUtank_53 "分柜欠压告警消除回差阈值";
CM_ SG_ 2416897654 S2P_Lmt6_Under_Utank1_54 "电池簇放电电压一级报警值";
CM_ SG_ 2416897654 S2P_Lmt6_Under_Utank2_54 "电池簇放电电压二级报警值";
CM_ SG_ 2416897654 S2P_Lmt6_Under_Utank3_54 "电池簇放电电压三级报警值";
CM_ SG_ 2416897654 S2P_Lmt6_Under_DUtank_54 "分柜欠压告警消除回差阈值";
CM_ SG_ 2416897655 S2P_Lmt6_Under_Utank1_55 "电池簇放电电压一级报警值";
CM_ SG_ 2416897655 S2P_Lmt6_Under_Utank2_55 "电池簇放电电压二级报警值";
CM_ SG_ 2416897655 S2P_Lmt6_Under_Utank3_55 "电池簇放电电压三级报警值";
CM_ SG_ 2416897655 S2P_Lmt6_Under_DUtank_55 "分柜欠压告警消除回差阈值";
CM_ SG_ 2416897656 S2P_Lmt6_Under_Utank1_56 "电池簇放电电压一级报警值";
CM_ SG_ 2416897656 S2P_Lmt6_Under_Utank2_56 "电池簇放电电压二级报警值";
CM_ SG_ 2416897656 S2P_Lmt6_Under_Utank3_56 "电池簇放电电压三级报警值";
CM_ SG_ 2416897656 S2P_Lmt6_Under_DUtank_56 "分柜欠压告警消除回差阈值";
CM_ SG_ 2416897657 S2P_Lmt6_Under_Utank1_57 "电池簇放电电压一级报警值";
CM_ SG_ 2416897657 S2P_Lmt6_Under_Utank2_57 "电池簇放电电压二级报警值";
CM_ SG_ 2416897657 S2P_Lmt6_Under_Utank3_57 "电池簇放电电压三级报警值";
CM_ SG_ 2416897657 S2P_Lmt6_Under_DUtank_57 "分柜欠压告警消除回差阈值";
CM_ SG_ 2416897658 S2P_Lmt6_Under_Utank1_58 "电池簇放电电压一级报警值";
CM_ SG_ 2416897658 S2P_Lmt6_Under_Utank2_58 "电池簇放电电压二级报警值";
CM_ SG_ 2416897658 S2P_Lmt6_Under_Utank3_58 "电池簇放电电压三级报警值";
CM_ SG_ 2416897658 S2P_Lmt6_Under_DUtank_58 "分柜欠压告警消除回差阈值";
CM_ SG_ 2416897659 S2P_Lmt6_Under_Utank1_59 "电池簇放电电压一级报警值";
CM_ SG_ 2416897659 S2P_Lmt6_Under_Utank2_59 "电池簇放电电压二级报警值";
CM_ SG_ 2416897659 S2P_Lmt6_Under_Utank3_59 "电池簇放电电压三级报警值";
CM_ SG_ 2416897659 S2P_Lmt6_Under_DUtank_59 "分柜欠压告警消除回差阈值";
CM_ SG_ 2416897660 S2P_Lmt6_Under_Utank1_60 "电池簇放电电压一级报警值";
CM_ SG_ 2416897660 S2P_Lmt6_Under_Utank2_60 "电池簇放电电压二级报警值";
CM_ SG_ 2416897660 S2P_Lmt6_Under_Utank3_60 "电池簇放电电压三级报警值";
CM_ SG_ 2416897660 S2P_Lmt6_Under_DUtank_60 "分柜欠压告警消除回差阈值";
CM_ SG_ 2416897661 S2P_Lmt6_Under_Utank1_61 "电池簇放电电压一级报警值";
CM_ SG_ 2416897661 S2P_Lmt6_Under_Utank2_61 "电池簇放电电压二级报警值";
CM_ SG_ 2416897661 S2P_Lmt6_Under_Utank3_61 "电池簇放电电压三级报警值";
CM_ SG_ 2416897661 S2P_Lmt6_Under_DUtank_61 "分柜欠压告警消除回差阈值";
CM_ SG_ 2416897662 S2P_Lmt6_Under_Utank1_62 "电池簇放电电压一级报警值";
CM_ SG_ 2416897662 S2P_Lmt6_Under_Utank2_62 "电池簇放电电压二级报警值";
CM_ SG_ 2416897662 S2P_Lmt6_Under_Utank3_62 "电池簇放电电压三级报警值";
CM_ SG_ 2416897662 S2P_Lmt6_Under_DUtank_62 "分柜欠压告警消除回差阈值";
CM_ SG_ 2416897663 S2P_Lmt6_Under_Utank1_63 "电池簇放电电压一级报警值";
CM_ SG_ 2416897663 S2P_Lmt6_Under_Utank2_63 "电池簇放电电压二级报警值";
CM_ SG_ 2416897663 S2P_Lmt6_Under_Utank3_63 "电池簇放电电压三级报警值";
CM_ SG_ 2416897663 S2P_Lmt6_Under_DUtank_63 "分柜欠压告警消除回差阈值";
CM_ SG_ 2416963137 S2P_Lmt7_Extreme_UcellMax_01 "单体电池电压极高值";
CM_ SG_ 2416963137 S2P_Lmt7_Extreme_UcellMin_01 "单体电池电压极低值";
CM_ SG_ 2416963137 S2P_Lmt7_Extreme_TcellMax_01 "单体电池温度极高值";
CM_ SG_ 2416963137 S2P_Lmt7_Extreme_TcellMin_01 "单体电池温度极低值";
CM_ SG_ 2416963138 S2P_Lmt7_Extreme_UcellMax_02 "单体电池电压极高值";
CM_ SG_ 2416963138 S2P_Lmt7_Extreme_UcellMin_02 "单体电池电压极低值";
CM_ SG_ 2416963138 S2P_Lmt7_Extreme_TcellMax_02 "单体电池温度极高值";
CM_ SG_ 2416963138 S2P_Lmt7_Extreme_TcellMin_02 "单体电池温度极低值";
CM_ SG_ 2416963139 S2P_Lmt7_Extreme_UcellMax_03 "单体电池电压极高值";
CM_ SG_ 2416963139 S2P_Lmt7_Extreme_UcellMin_03 "单体电池电压极低值";
CM_ SG_ 2416963139 S2P_Lmt7_Extreme_TcellMax_03 "单体电池温度极高值";
CM_ SG_ 2416963139 S2P_Lmt7_Extreme_TcellMin_03 "单体电池温度极低值";
CM_ SG_ 2416963140 S2P_Lmt7_Extreme_UcellMax_04 "单体电池电压极高值";
CM_ SG_ 2416963140 S2P_Lmt7_Extreme_UcellMin_04 "单体电池电压极低值";
CM_ SG_ 2416963140 S2P_Lmt7_Extreme_TcellMax_04 "单体电池温度极高值";
CM_ SG_ 2416963140 S2P_Lmt7_Extreme_TcellMin_04 "单体电池温度极低值";
CM_ SG_ 2416963141 S2P_Lmt7_Extreme_UcellMax_05 "单体电池电压极高值";
CM_ SG_ 2416963141 S2P_Lmt7_Extreme_UcellMin_05 "单体电池电压极低值";
CM_ SG_ 2416963141 S2P_Lmt7_Extreme_TcellMax_05 "单体电池温度极高值";
CM_ SG_ 2416963141 S2P_Lmt7_Extreme_TcellMin_05 "单体电池温度极低值";
CM_ SG_ 2416963142 S2P_Lmt7_Extreme_UcellMax_06 "单体电池电压极高值";
CM_ SG_ 2416963142 S2P_Lmt7_Extreme_UcellMin_06 "单体电池电压极低值";
CM_ SG_ 2416963142 S2P_Lmt7_Extreme_TcellMax_06 "单体电池温度极高值";
CM_ SG_ 2416963142 S2P_Lmt7_Extreme_TcellMin_06 "单体电池温度极低值";
CM_ SG_ 2416963143 S2P_Lmt7_Extreme_UcellMax_07 "单体电池电压极高值";
CM_ SG_ 2416963143 S2P_Lmt7_Extreme_UcellMin_07 "单体电池电压极低值";
CM_ SG_ 2416963143 S2P_Lmt7_Extreme_TcellMax_07 "单体电池温度极高值";
CM_ SG_ 2416963143 S2P_Lmt7_Extreme_TcellMin_07 "单体电池温度极低值";
CM_ SG_ 2416963144 S2P_Lmt7_Extreme_UcellMax_08 "单体电池电压极高值";
CM_ SG_ 2416963144 S2P_Lmt7_Extreme_UcellMin_08 "单体电池电压极低值";
CM_ SG_ 2416963144 S2P_Lmt7_Extreme_TcellMax_08 "单体电池温度极高值";
CM_ SG_ 2416963144 S2P_Lmt7_Extreme_TcellMin_08 "单体电池温度极低值";
CM_ SG_ 2416963145 S2P_Lmt7_Extreme_UcellMax_09 "单体电池电压极高值";
CM_ SG_ 2416963145 S2P_Lmt7_Extreme_UcellMin_09 "单体电池电压极低值";
CM_ SG_ 2416963145 S2P_Lmt7_Extreme_TcellMax_09 "单体电池温度极高值";
CM_ SG_ 2416963145 S2P_Lmt7_Extreme_TcellMin_09 "单体电池温度极低值";
CM_ SG_ 2416963146 S2P_Lmt7_Extreme_UcellMax_10 "单体电池电压极高值";
CM_ SG_ 2416963146 S2P_Lmt7_Extreme_UcellMin_10 "单体电池电压极低值";
CM_ SG_ 2416963146 S2P_Lmt7_Extreme_TcellMax_10 "单体电池温度极高值";
CM_ SG_ 2416963146 S2P_Lmt7_Extreme_TcellMin_10 "单体电池温度极低值";
CM_ SG_ 2416963147 S2P_Lmt7_Extreme_UcellMax_11 "单体电池电压极高值";
CM_ SG_ 2416963147 S2P_Lmt7_Extreme_UcellMin_11 "单体电池电压极低值";
CM_ SG_ 2416963147 S2P_Lmt7_Extreme_TcellMax_11 "单体电池温度极高值";
CM_ SG_ 2416963147 S2P_Lmt7_Extreme_TcellMin_11 "单体电池温度极低值";
CM_ SG_ 2416963148 S2P_Lmt7_Extreme_UcellMax_12 "单体电池电压极高值";
CM_ SG_ 2416963148 S2P_Lmt7_Extreme_UcellMin_12 "单体电池电压极低值";
CM_ SG_ 2416963148 S2P_Lmt7_Extreme_TcellMax_12 "单体电池温度极高值";
CM_ SG_ 2416963148 S2P_Lmt7_Extreme_TcellMin_12 "单体电池温度极低值";
CM_ SG_ 2416963149 S2P_Lmt7_Extreme_UcellMax_13 "单体电池电压极高值";
CM_ SG_ 2416963149 S2P_Lmt7_Extreme_UcellMin_13 "单体电池电压极低值";
CM_ SG_ 2416963149 S2P_Lmt7_Extreme_TcellMax_13 "单体电池温度极高值";
CM_ SG_ 2416963149 S2P_Lmt7_Extreme_TcellMin_13 "单体电池温度极低值";
CM_ SG_ 2416963150 S2P_Lmt7_Extreme_UcellMax_14 "单体电池电压极高值";
CM_ SG_ 2416963150 S2P_Lmt7_Extreme_UcellMin_14 "单体电池电压极低值";
CM_ SG_ 2416963150 S2P_Lmt7_Extreme_TcellMax_14 "单体电池温度极高值";
CM_ SG_ 2416963150 S2P_Lmt7_Extreme_TcellMin_14 "单体电池温度极低值";
CM_ SG_ 2416963151 S2P_Lmt7_Extreme_UcellMax_15 "单体电池电压极高值";
CM_ SG_ 2416963151 S2P_Lmt7_Extreme_UcellMin_15 "单体电池电压极低值";
CM_ SG_ 2416963151 S2P_Lmt7_Extreme_TcellMax_15 "单体电池温度极高值";
CM_ SG_ 2416963151 S2P_Lmt7_Extreme_TcellMin_15 "单体电池温度极低值";
CM_ SG_ 2416963152 S2P_Lmt7_Extreme_UcellMax_16 "单体电池电压极高值";
CM_ SG_ 2416963152 S2P_Lmt7_Extreme_UcellMin_16 "单体电池电压极低值";
CM_ SG_ 2416963152 S2P_Lmt7_Extreme_TcellMax_16 "单体电池温度极高值";
CM_ SG_ 2416963152 S2P_Lmt7_Extreme_TcellMin_16 "单体电池温度极低值";
CM_ SG_ 2416963153 S2P_Lmt7_Extreme_UcellMax_17 "单体电池电压极高值";
CM_ SG_ 2416963153 S2P_Lmt7_Extreme_UcellMin_17 "单体电池电压极低值";
CM_ SG_ 2416963153 S2P_Lmt7_Extreme_TcellMax_17 "单体电池温度极高值";
CM_ SG_ 2416963153 S2P_Lmt7_Extreme_TcellMin_17 "单体电池温度极低值";
CM_ SG_ 2416963154 S2P_Lmt7_Extreme_UcellMax_18 "单体电池电压极高值";
CM_ SG_ 2416963154 S2P_Lmt7_Extreme_UcellMin_18 "单体电池电压极低值";
CM_ SG_ 2416963154 S2P_Lmt7_Extreme_TcellMax_18 "单体电池温度极高值";
CM_ SG_ 2416963154 S2P_Lmt7_Extreme_TcellMin_18 "单体电池温度极低值";
CM_ SG_ 2416963155 S2P_Lmt7_Extreme_UcellMax_19 "单体电池电压极高值";
CM_ SG_ 2416963155 S2P_Lmt7_Extreme_UcellMin_19 "单体电池电压极低值";
CM_ SG_ 2416963155 S2P_Lmt7_Extreme_TcellMax_19 "单体电池温度极高值";
CM_ SG_ 2416963155 S2P_Lmt7_Extreme_TcellMin_19 "单体电池温度极低值";
CM_ SG_ 2416963156 S2P_Lmt7_Extreme_UcellMax_20 "单体电池电压极高值";
CM_ SG_ 2416963156 S2P_Lmt7_Extreme_UcellMin_20 "单体电池电压极低值";
CM_ SG_ 2416963156 S2P_Lmt7_Extreme_TcellMax_20 "单体电池温度极高值";
CM_ SG_ 2416963156 S2P_Lmt7_Extreme_TcellMin_20 "单体电池温度极低值";
CM_ SG_ 2416963157 S2P_Lmt7_Extreme_UcellMax_21 "单体电池电压极高值";
CM_ SG_ 2416963157 S2P_Lmt7_Extreme_UcellMin_21 "单体电池电压极低值";
CM_ SG_ 2416963157 S2P_Lmt7_Extreme_TcellMax_21 "单体电池温度极高值";
CM_ SG_ 2416963157 S2P_Lmt7_Extreme_TcellMin_21 "单体电池温度极低值";
CM_ SG_ 2416963158 S2P_Lmt7_Extreme_UcellMax_22 "单体电池电压极高值";
CM_ SG_ 2416963158 S2P_Lmt7_Extreme_UcellMin_22 "单体电池电压极低值";
CM_ SG_ 2416963158 S2P_Lmt7_Extreme_TcellMax_22 "单体电池温度极高值";
CM_ SG_ 2416963158 S2P_Lmt7_Extreme_TcellMin_22 "单体电池温度极低值";
CM_ SG_ 2416963159 S2P_Lmt7_Extreme_UcellMax_23 "单体电池电压极高值";
CM_ SG_ 2416963159 S2P_Lmt7_Extreme_UcellMin_23 "单体电池电压极低值";
CM_ SG_ 2416963159 S2P_Lmt7_Extreme_TcellMax_23 "单体电池温度极高值";
CM_ SG_ 2416963159 S2P_Lmt7_Extreme_TcellMin_23 "单体电池温度极低值";
CM_ SG_ 2416963160 S2P_Lmt7_Extreme_UcellMax_24 "单体电池电压极高值";
CM_ SG_ 2416963160 S2P_Lmt7_Extreme_UcellMin_24 "单体电池电压极低值";
CM_ SG_ 2416963160 S2P_Lmt7_Extreme_TcellMax_24 "单体电池温度极高值";
CM_ SG_ 2416963160 S2P_Lmt7_Extreme_TcellMin_24 "单体电池温度极低值";
CM_ SG_ 2416963161 S2P_Lmt7_Extreme_UcellMax_25 "单体电池电压极高值";
CM_ SG_ 2416963161 S2P_Lmt7_Extreme_UcellMin_25 "单体电池电压极低值";
CM_ SG_ 2416963161 S2P_Lmt7_Extreme_TcellMax_25 "单体电池温度极高值";
CM_ SG_ 2416963161 S2P_Lmt7_Extreme_TcellMin_25 "单体电池温度极低值";
CM_ SG_ 2416963162 S2P_Lmt7_Extreme_UcellMax_26 "单体电池电压极高值";
CM_ SG_ 2416963162 S2P_Lmt7_Extreme_UcellMin_26 "单体电池电压极低值";
CM_ SG_ 2416963162 S2P_Lmt7_Extreme_TcellMax_26 "单体电池温度极高值";
CM_ SG_ 2416963162 S2P_Lmt7_Extreme_TcellMin_26 "单体电池温度极低值";
CM_ SG_ 2416963163 S2P_Lmt7_Extreme_UcellMax_27 "单体电池电压极高值";
CM_ SG_ 2416963163 S2P_Lmt7_Extreme_UcellMin_27 "单体电池电压极低值";
CM_ SG_ 2416963163 S2P_Lmt7_Extreme_TcellMax_27 "单体电池温度极高值";
CM_ SG_ 2416963163 S2P_Lmt7_Extreme_TcellMin_27 "单体电池温度极低值";
CM_ SG_ 2416963164 S2P_Lmt7_Extreme_UcellMax_28 "单体电池电压极高值";
CM_ SG_ 2416963164 S2P_Lmt7_Extreme_UcellMin_28 "单体电池电压极低值";
CM_ SG_ 2416963164 S2P_Lmt7_Extreme_TcellMax_28 "单体电池温度极高值";
CM_ SG_ 2416963164 S2P_Lmt7_Extreme_TcellMin_28 "单体电池温度极低值";
CM_ SG_ 2416963165 S2P_Lmt7_Extreme_UcellMax_29 "单体电池电压极高值";
CM_ SG_ 2416963165 S2P_Lmt7_Extreme_UcellMin_29 "单体电池电压极低值";
CM_ SG_ 2416963165 S2P_Lmt7_Extreme_TcellMax_29 "单体电池温度极高值";
CM_ SG_ 2416963165 S2P_Lmt7_Extreme_TcellMin_29 "单体电池温度极低值";
CM_ SG_ 2416963166 S2P_Lmt7_Extreme_UcellMax_30 "单体电池电压极高值";
CM_ SG_ 2416963166 S2P_Lmt7_Extreme_UcellMin_30 "单体电池电压极低值";
CM_ SG_ 2416963166 S2P_Lmt7_Extreme_TcellMax_30 "单体电池温度极高值";
CM_ SG_ 2416963166 S2P_Lmt7_Extreme_TcellMin_30 "单体电池温度极低值";
CM_ SG_ 2416963167 S2P_Lmt7_Extreme_UcellMax_31 "单体电池电压极高值";
CM_ SG_ 2416963167 S2P_Lmt7_Extreme_UcellMin_31 "单体电池电压极低值";
CM_ SG_ 2416963167 S2P_Lmt7_Extreme_TcellMax_31 "单体电池温度极高值";
CM_ SG_ 2416963167 S2P_Lmt7_Extreme_TcellMin_31 "单体电池温度极低值";
CM_ SG_ 2416963168 S2P_Lmt7_Extreme_UcellMax_32 "单体电池电压极高值";
CM_ SG_ 2416963168 S2P_Lmt7_Extreme_UcellMin_32 "单体电池电压极低值";
CM_ SG_ 2416963168 S2P_Lmt7_Extreme_TcellMax_32 "单体电池温度极高值";
CM_ SG_ 2416963168 S2P_Lmt7_Extreme_TcellMin_32 "单体电池温度极低值";
CM_ SG_ 2416963169 S2P_Lmt7_Extreme_UcellMax_33 "单体电池电压极高值";
CM_ SG_ 2416963169 S2P_Lmt7_Extreme_UcellMin_33 "单体电池电压极低值";
CM_ SG_ 2416963169 S2P_Lmt7_Extreme_TcellMax_33 "单体电池温度极高值";
CM_ SG_ 2416963169 S2P_Lmt7_Extreme_TcellMin_33 "单体电池温度极低值";
CM_ SG_ 2416963170 S2P_Lmt7_Extreme_UcellMax_34 "单体电池电压极高值";
CM_ SG_ 2416963170 S2P_Lmt7_Extreme_UcellMin_34 "单体电池电压极低值";
CM_ SG_ 2416963170 S2P_Lmt7_Extreme_TcellMax_34 "单体电池温度极高值";
CM_ SG_ 2416963170 S2P_Lmt7_Extreme_TcellMin_34 "单体电池温度极低值";
CM_ SG_ 2416963171 S2P_Lmt7_Extreme_UcellMax_35 "单体电池电压极高值";
CM_ SG_ 2416963171 S2P_Lmt7_Extreme_UcellMin_35 "单体电池电压极低值";
CM_ SG_ 2416963171 S2P_Lmt7_Extreme_TcellMax_35 "单体电池温度极高值";
CM_ SG_ 2416963171 S2P_Lmt7_Extreme_TcellMin_35 "单体电池温度极低值";
CM_ SG_ 2416963172 S2P_Lmt7_Extreme_UcellMax_36 "单体电池电压极高值";
CM_ SG_ 2416963172 S2P_Lmt7_Extreme_UcellMin_36 "单体电池电压极低值";
CM_ SG_ 2416963172 S2P_Lmt7_Extreme_TcellMax_36 "单体电池温度极高值";
CM_ SG_ 2416963172 S2P_Lmt7_Extreme_TcellMin_36 "单体电池温度极低值";
CM_ SG_ 2416963173 S2P_Lmt7_Extreme_UcellMax_37 "单体电池电压极高值";
CM_ SG_ 2416963173 S2P_Lmt7_Extreme_UcellMin_37 "单体电池电压极低值";
CM_ SG_ 2416963173 S2P_Lmt7_Extreme_TcellMax_37 "单体电池温度极高值";
CM_ SG_ 2416963173 S2P_Lmt7_Extreme_TcellMin_37 "单体电池温度极低值";
CM_ SG_ 2416963174 S2P_Lmt7_Extreme_UcellMax_38 "单体电池电压极高值";
CM_ SG_ 2416963174 S2P_Lmt7_Extreme_UcellMin_38 "单体电池电压极低值";
CM_ SG_ 2416963174 S2P_Lmt7_Extreme_TcellMax_38 "单体电池温度极高值";
CM_ SG_ 2416963174 S2P_Lmt7_Extreme_TcellMin_38 "单体电池温度极低值";
CM_ SG_ 2416963175 S2P_Lmt7_Extreme_UcellMax_39 "单体电池电压极高值";
CM_ SG_ 2416963175 S2P_Lmt7_Extreme_UcellMin_39 "单体电池电压极低值";
CM_ SG_ 2416963175 S2P_Lmt7_Extreme_TcellMax_39 "单体电池温度极高值";
CM_ SG_ 2416963175 S2P_Lmt7_Extreme_TcellMin_39 "单体电池温度极低值";
CM_ SG_ 2416963176 S2P_Lmt7_Extreme_UcellMax_40 "单体电池电压极高值";
CM_ SG_ 2416963176 S2P_Lmt7_Extreme_UcellMin_40 "单体电池电压极低值";
CM_ SG_ 2416963176 S2P_Lmt7_Extreme_TcellMax_40 "单体电池温度极高值";
CM_ SG_ 2416963176 S2P_Lmt7_Extreme_TcellMin_40 "单体电池温度极低值";
CM_ SG_ 2416963177 S2P_Lmt7_Extreme_UcellMax_41 "单体电池电压极高值";
CM_ SG_ 2416963177 S2P_Lmt7_Extreme_UcellMin_41 "单体电池电压极低值";
CM_ SG_ 2416963177 S2P_Lmt7_Extreme_TcellMax_41 "单体电池温度极高值";
CM_ SG_ 2416963177 S2P_Lmt7_Extreme_TcellMin_41 "单体电池温度极低值";
CM_ SG_ 2416963178 S2P_Lmt7_Extreme_UcellMax_42 "单体电池电压极高值";
CM_ SG_ 2416963178 S2P_Lmt7_Extreme_UcellMin_42 "单体电池电压极低值";
CM_ SG_ 2416963178 S2P_Lmt7_Extreme_TcellMax_42 "单体电池温度极高值";
CM_ SG_ 2416963178 S2P_Lmt7_Extreme_TcellMin_42 "单体电池温度极低值";
CM_ SG_ 2416963179 S2P_Lmt7_Extreme_UcellMax_43 "单体电池电压极高值";
CM_ SG_ 2416963179 S2P_Lmt7_Extreme_UcellMin_43 "单体电池电压极低值";
CM_ SG_ 2416963179 S2P_Lmt7_Extreme_TcellMax_43 "单体电池温度极高值";
CM_ SG_ 2416963179 S2P_Lmt7_Extreme_TcellMin_43 "单体电池温度极低值";
CM_ SG_ 2416963180 S2P_Lmt7_Extreme_UcellMax_44 "单体电池电压极高值";
CM_ SG_ 2416963180 S2P_Lmt7_Extreme_UcellMin_44 "单体电池电压极低值";
CM_ SG_ 2416963180 S2P_Lmt7_Extreme_TcellMax_44 "单体电池温度极高值";
CM_ SG_ 2416963180 S2P_Lmt7_Extreme_TcellMin_44 "单体电池温度极低值";
CM_ SG_ 2416963181 S2P_Lmt7_Extreme_UcellMax_45 "单体电池电压极高值";
CM_ SG_ 2416963181 S2P_Lmt7_Extreme_UcellMin_45 "单体电池电压极低值";
CM_ SG_ 2416963181 S2P_Lmt7_Extreme_TcellMax_45 "单体电池温度极高值";
CM_ SG_ 2416963181 S2P_Lmt7_Extreme_TcellMin_45 "单体电池温度极低值";
CM_ SG_ 2416963182 S2P_Lmt7_Extreme_UcellMax_46 "单体电池电压极高值";
CM_ SG_ 2416963182 S2P_Lmt7_Extreme_UcellMin_46 "单体电池电压极低值";
CM_ SG_ 2416963182 S2P_Lmt7_Extreme_TcellMax_46 "单体电池温度极高值";
CM_ SG_ 2416963182 S2P_Lmt7_Extreme_TcellMin_46 "单体电池温度极低值";
CM_ SG_ 2416963183 S2P_Lmt7_Extreme_UcellMax_47 "单体电池电压极高值";
CM_ SG_ 2416963183 S2P_Lmt7_Extreme_UcellMin_47 "单体电池电压极低值";
CM_ SG_ 2416963183 S2P_Lmt7_Extreme_TcellMax_47 "单体电池温度极高值";
CM_ SG_ 2416963183 S2P_Lmt7_Extreme_TcellMin_47 "单体电池温度极低值";
CM_ SG_ 2416963184 S2P_Lmt7_Extreme_UcellMax_48 "单体电池电压极高值";
CM_ SG_ 2416963184 S2P_Lmt7_Extreme_UcellMin_48 "单体电池电压极低值";
CM_ SG_ 2416963184 S2P_Lmt7_Extreme_TcellMax_48 "单体电池温度极高值";
CM_ SG_ 2416963184 S2P_Lmt7_Extreme_TcellMin_48 "单体电池温度极低值";
CM_ SG_ 2416963185 S2P_Lmt7_Extreme_UcellMax_49 "单体电池电压极高值";
CM_ SG_ 2416963185 S2P_Lmt7_Extreme_UcellMin_49 "单体电池电压极低值";
CM_ SG_ 2416963185 S2P_Lmt7_Extreme_TcellMax_49 "单体电池温度极高值";
CM_ SG_ 2416963185 S2P_Lmt7_Extreme_TcellMin_49 "单体电池温度极低值";
CM_ SG_ 2416963186 S2P_Lmt7_Extreme_UcellMax_50 "单体电池电压极高值";
CM_ SG_ 2416963186 S2P_Lmt7_Extreme_UcellMin_50 "单体电池电压极低值";
CM_ SG_ 2416963186 S2P_Lmt7_Extreme_TcellMax_50 "单体电池温度极高值";
CM_ SG_ 2416963186 S2P_Lmt7_Extreme_TcellMin_50 "单体电池温度极低值";
CM_ SG_ 2416963187 S2P_Lmt7_Extreme_UcellMax_51 "单体电池电压极高值";
CM_ SG_ 2416963187 S2P_Lmt7_Extreme_UcellMin_51 "单体电池电压极低值";
CM_ SG_ 2416963187 S2P_Lmt7_Extreme_TcellMax_51 "单体电池温度极高值";
CM_ SG_ 2416963187 S2P_Lmt7_Extreme_TcellMin_51 "单体电池温度极低值";
CM_ SG_ 2416963188 S2P_Lmt7_Extreme_UcellMax_52 "单体电池电压极高值";
CM_ SG_ 2416963188 S2P_Lmt7_Extreme_UcellMin_52 "单体电池电压极低值";
CM_ SG_ 2416963188 S2P_Lmt7_Extreme_TcellMax_52 "单体电池温度极高值";
CM_ SG_ 2416963188 S2P_Lmt7_Extreme_TcellMin_52 "单体电池温度极低值";
CM_ SG_ 2416963189 S2P_Lmt7_Extreme_UcellMax_53 "单体电池电压极高值";
CM_ SG_ 2416963189 S2P_Lmt7_Extreme_UcellMin_53 "单体电池电压极低值";
CM_ SG_ 2416963189 S2P_Lmt7_Extreme_TcellMax_53 "单体电池温度极高值";
CM_ SG_ 2416963189 S2P_Lmt7_Extreme_TcellMin_53 "单体电池温度极低值";
CM_ SG_ 2416963190 S2P_Lmt7_Extreme_UcellMax_54 "单体电池电压极高值";
CM_ SG_ 2416963190 S2P_Lmt7_Extreme_UcellMin_54 "单体电池电压极低值";
CM_ SG_ 2416963190 S2P_Lmt7_Extreme_TcellMax_54 "单体电池温度极高值";
CM_ SG_ 2416963190 S2P_Lmt7_Extreme_TcellMin_54 "单体电池温度极低值";
CM_ SG_ 2416963191 S2P_Lmt7_Extreme_UcellMax_55 "单体电池电压极高值";
CM_ SG_ 2416963191 S2P_Lmt7_Extreme_UcellMin_55 "单体电池电压极低值";
CM_ SG_ 2416963191 S2P_Lmt7_Extreme_TcellMax_55 "单体电池温度极高值";
CM_ SG_ 2416963191 S2P_Lmt7_Extreme_TcellMin_55 "单体电池温度极低值";
CM_ SG_ 2416963192 S2P_Lmt7_Extreme_UcellMax_56 "单体电池电压极高值";
CM_ SG_ 2416963192 S2P_Lmt7_Extreme_UcellMin_56 "单体电池电压极低值";
CM_ SG_ 2416963192 S2P_Lmt7_Extreme_TcellMax_56 "单体电池温度极高值";
CM_ SG_ 2416963192 S2P_Lmt7_Extreme_TcellMin_56 "单体电池温度极低值";
CM_ SG_ 2416963193 S2P_Lmt7_Extreme_UcellMax_57 "单体电池电压极高值";
CM_ SG_ 2416963193 S2P_Lmt7_Extreme_UcellMin_57 "单体电池电压极低值";
CM_ SG_ 2416963193 S2P_Lmt7_Extreme_TcellMax_57 "单体电池温度极高值";
CM_ SG_ 2416963193 S2P_Lmt7_Extreme_TcellMin_57 "单体电池温度极低值";
CM_ SG_ 2416963194 S2P_Lmt7_Extreme_UcellMax_58 "单体电池电压极高值";
CM_ SG_ 2416963194 S2P_Lmt7_Extreme_UcellMin_58 "单体电池电压极低值";
CM_ SG_ 2416963194 S2P_Lmt7_Extreme_TcellMax_58 "单体电池温度极高值";
CM_ SG_ 2416963194 S2P_Lmt7_Extreme_TcellMin_58 "单体电池温度极低值";
CM_ SG_ 2416963195 S2P_Lmt7_Extreme_UcellMax_59 "单体电池电压极高值";
CM_ SG_ 2416963195 S2P_Lmt7_Extreme_UcellMin_59 "单体电池电压极低值";
CM_ SG_ 2416963195 S2P_Lmt7_Extreme_TcellMax_59 "单体电池温度极高值";
CM_ SG_ 2416963195 S2P_Lmt7_Extreme_TcellMin_59 "单体电池温度极低值";
CM_ SG_ 2416963196 S2P_Lmt7_Extreme_UcellMax_60 "单体电池电压极高值";
CM_ SG_ 2416963196 S2P_Lmt7_Extreme_UcellMin_60 "单体电池电压极低值";
CM_ SG_ 2416963196 S2P_Lmt7_Extreme_TcellMax_60 "单体电池温度极高值";
CM_ SG_ 2416963196 S2P_Lmt7_Extreme_TcellMin_60 "单体电池温度极低值";
CM_ SG_ 2416963197 S2P_Lmt7_Extreme_UcellMax_61 "单体电池电压极高值";
CM_ SG_ 2416963197 S2P_Lmt7_Extreme_UcellMin_61 "单体电池电压极低值";
CM_ SG_ 2416963197 S2P_Lmt7_Extreme_TcellMax_61 "单体电池温度极高值";
CM_ SG_ 2416963197 S2P_Lmt7_Extreme_TcellMin_61 "单体电池温度极低值";
CM_ SG_ 2416963198 S2P_Lmt7_Extreme_UcellMax_62 "单体电池电压极高值";
CM_ SG_ 2416963198 S2P_Lmt7_Extreme_UcellMin_62 "单体电池电压极低值";
CM_ SG_ 2416963198 S2P_Lmt7_Extreme_TcellMax_62 "单体电池温度极高值";
CM_ SG_ 2416963198 S2P_Lmt7_Extreme_TcellMin_62 "单体电池温度极低值";
CM_ SG_ 2416963199 S2P_Lmt7_Extreme_UcellMax_63 "单体电池电压极高值";
CM_ SG_ 2416963199 S2P_Lmt7_Extreme_UcellMin_63 "单体电池电压极低值";
CM_ SG_ 2416963199 S2P_Lmt7_Extreme_TcellMax_63 "单体电池温度极高值";
CM_ SG_ 2416963199 S2P_Lmt7_Extreme_TcellMin_63 "单体电池温度极低值";
CM_ SG_ 2417028673 S2P_Lmt8_OverCLongThanN1_Time_01 "1级过流时间过长告警的时间阈值(时间超过N1)(预留)";
CM_ SG_ 2417028673 S2P_Lmt8_OverCLongThanN2_Time_01 "2级过流时间过长告警的时间阈值(时间超过N2)(预留)";
CM_ SG_ 2417028673 S2P_Lmt8_OverCLongThanN3_Time_01 "3级过流时间过长告警的时间阈值(时间超过N3)(预留)";
CM_ SG_ 2417028674 S2P_Lmt8_OverCLongThanN1_Time_02 "1级过流时间过长告警的时间阈值(时间超过N1)(预留)";
CM_ SG_ 2417028674 S2P_Lmt8_OverCLongThanN2_Time_02 "2级过流时间过长告警的时间阈值(时间超过N2)(预留)";
CM_ SG_ 2417028674 S2P_Lmt8_OverCLongThanN3_Time_02 "3级过流时间过长告警的时间阈值(时间超过N3)(预留)";
CM_ SG_ 2417028675 S2P_Lmt8_OverCLongThanN1_Time_03 "1级过流时间过长告警的时间阈值(时间超过N1)(预留)";
CM_ SG_ 2417028675 S2P_Lmt8_OverCLongThanN2_Time_03 "2级过流时间过长告警的时间阈值(时间超过N2)(预留)";
CM_ SG_ 2417028675 S2P_Lmt8_OverCLongThanN3_Time_03 "3级过流时间过长告警的时间阈值(时间超过N3)(预留)";
CM_ SG_ 2417028676 S2P_Lmt8_OverCLongThanN1_Time_04 "1级过流时间过长告警的时间阈值(时间超过N1)(预留)";
CM_ SG_ 2417028676 S2P_Lmt8_OverCLongThanN2_Time_04 "2级过流时间过长告警的时间阈值(时间超过N2)(预留)";
CM_ SG_ 2417028676 S2P_Lmt8_OverCLongThanN3_Time_04 "3级过流时间过长告警的时间阈值(时间超过N3)(预留)";
CM_ SG_ 2417028677 S2P_Lmt8_OverCLongThanN1_Time_05 "1级过流时间过长告警的时间阈值(时间超过N1)(预留)";
CM_ SG_ 2417028677 S2P_Lmt8_OverCLongThanN2_Time_05 "2级过流时间过长告警的时间阈值(时间超过N2)(预留)";
CM_ SG_ 2417028677 S2P_Lmt8_OverCLongThanN3_Time_05 "3级过流时间过长告警的时间阈值(时间超过N3)(预留)";
CM_ SG_ 2417028678 S2P_Lmt8_OverCLongThanN1_Time_06 "1级过流时间过长告警的时间阈值(时间超过N1)(预留)";
CM_ SG_ 2417028678 S2P_Lmt8_OverCLongThanN2_Time_06 "2级过流时间过长告警的时间阈值(时间超过N2)(预留)";
CM_ SG_ 2417028678 S2P_Lmt8_OverCLongThanN3_Time_06 "3级过流时间过长告警的时间阈值(时间超过N3)(预留)";
CM_ SG_ 2417028679 S2P_Lmt8_OverCLongThanN1_Time_07 "1级过流时间过长告警的时间阈值(时间超过N1)(预留)";
CM_ SG_ 2417028679 S2P_Lmt8_OverCLongThanN2_Time_07 "2级过流时间过长告警的时间阈值(时间超过N2)(预留)";
CM_ SG_ 2417028679 S2P_Lmt8_OverCLongThanN3_Time_07 "3级过流时间过长告警的时间阈值(时间超过N3)(预留)";
CM_ SG_ 2417028680 S2P_Lmt8_OverCLongThanN1_Time_08 "1级过流时间过长告警的时间阈值(时间超过N1)(预留)";
CM_ SG_ 2417028680 S2P_Lmt8_OverCLongThanN2_Time_08 "2级过流时间过长告警的时间阈值(时间超过N2)(预留)";
CM_ SG_ 2417028680 S2P_Lmt8_OverCLongThanN3_Time_08 "3级过流时间过长告警的时间阈值(时间超过N3)(预留)";
CM_ SG_ 2417028681 S2P_Lmt8_OverCLongThanN1_Time_09 "1级过流时间过长告警的时间阈值(时间超过N1)(预留)";
CM_ SG_ 2417028681 S2P_Lmt8_OverCLongThanN2_Time_09 "2级过流时间过长告警的时间阈值(时间超过N2)(预留)";
CM_ SG_ 2417028681 S2P_Lmt8_OverCLongThanN3_Time_09 "3级过流时间过长告警的时间阈值(时间超过N3)(预留)";
CM_ SG_ 2417028682 S2P_Lmt8_OverCLongThanN1_Time_10 "1级过流时间过长告警的时间阈值(时间超过N1)(预留)";
CM_ SG_ 2417028682 S2P_Lmt8_OverCLongThanN2_Time_10 "2级过流时间过长告警的时间阈值(时间超过N2)(预留)";
CM_ SG_ 2417028682 S2P_Lmt8_OverCLongThanN3_Time_10 "3级过流时间过长告警的时间阈值(时间超过N3)(预留)";
CM_ SG_ 2417028683 S2P_Lmt8_OverCLongThanN1_Time_11 "1级过流时间过长告警的时间阈值(时间超过N1)(预留)";
CM_ SG_ 2417028683 S2P_Lmt8_OverCLongThanN2_Time_11 "2级过流时间过长告警的时间阈值(时间超过N2)(预留)";
CM_ SG_ 2417028683 S2P_Lmt8_OverCLongThanN3_Time_11 "3级过流时间过长告警的时间阈值(时间超过N3)(预留)";
CM_ SG_ 2417028684 S2P_Lmt8_OverCLongThanN1_Time_12 "1级过流时间过长告警的时间阈值(时间超过N1)(预留)";
CM_ SG_ 2417028684 S2P_Lmt8_OverCLongThanN2_Time_12 "2级过流时间过长告警的时间阈值(时间超过N2)(预留)";
CM_ SG_ 2417028684 S2P_Lmt8_OverCLongThanN3_Time_12 "3级过流时间过长告警的时间阈值(时间超过N3)(预留)";
CM_ SG_ 2417028685 S2P_Lmt8_OverCLongThanN1_Time_13 "1级过流时间过长告警的时间阈值(时间超过N1)(预留)";
CM_ SG_ 2417028685 S2P_Lmt8_OverCLongThanN2_Time_13 "2级过流时间过长告警的时间阈值(时间超过N2)(预留)";
CM_ SG_ 2417028685 S2P_Lmt8_OverCLongThanN3_Time_13 "3级过流时间过长告警的时间阈值(时间超过N3)(预留)";
CM_ SG_ 2417028686 S2P_Lmt8_OverCLongThanN1_Time_14 "1级过流时间过长告警的时间阈值(时间超过N1)(预留)";
CM_ SG_ 2417028686 S2P_Lmt8_OverCLongThanN2_Time_14 "2级过流时间过长告警的时间阈值(时间超过N2)(预留)";
CM_ SG_ 2417028686 S2P_Lmt8_OverCLongThanN3_Time_14 "3级过流时间过长告警的时间阈值(时间超过N3)(预留)";
CM_ SG_ 2417028687 S2P_Lmt8_OverCLongThanN1_Time_15 "1级过流时间过长告警的时间阈值(时间超过N1)(预留)";
CM_ SG_ 2417028687 S2P_Lmt8_OverCLongThanN2_Time_15 "2级过流时间过长告警的时间阈值(时间超过N2)(预留)";
CM_ SG_ 2417028687 S2P_Lmt8_OverCLongThanN3_Time_15 "3级过流时间过长告警的时间阈值(时间超过N3)(预留)";
CM_ SG_ 2417028688 S2P_Lmt8_OverCLongThanN1_Time_16 "1级过流时间过长告警的时间阈值(时间超过N1)(预留)";
CM_ SG_ 2417028688 S2P_Lmt8_OverCLongThanN2_Time_16 "2级过流时间过长告警的时间阈值(时间超过N2)(预留)";
CM_ SG_ 2417028688 S2P_Lmt8_OverCLongThanN3_Time_16 "3级过流时间过长告警的时间阈值(时间超过N3)(预留)";
CM_ SG_ 2417028689 S2P_Lmt8_OverCLongThanN1_Time_17 "1级过流时间过长告警的时间阈值(时间超过N1)(预留)";
CM_ SG_ 2417028689 S2P_Lmt8_OverCLongThanN2_Time_17 "2级过流时间过长告警的时间阈值(时间超过N2)(预留)";
CM_ SG_ 2417028689 S2P_Lmt8_OverCLongThanN3_Time_17 "3级过流时间过长告警的时间阈值(时间超过N3)(预留)";
CM_ SG_ 2417028690 S2P_Lmt8_OverCLongThanN1_Time_18 "1级过流时间过长告警的时间阈值(时间超过N1)(预留)";
CM_ SG_ 2417028690 S2P_Lmt8_OverCLongThanN2_Time_18 "2级过流时间过长告警的时间阈值(时间超过N2)(预留)";
CM_ SG_ 2417028690 S2P_Lmt8_OverCLongThanN3_Time_18 "3级过流时间过长告警的时间阈值(时间超过N3)(预留)";
CM_ SG_ 2417028691 S2P_Lmt8_OverCLongThanN1_Time_19 "1级过流时间过长告警的时间阈值(时间超过N1)(预留)";
CM_ SG_ 2417028691 S2P_Lmt8_OverCLongThanN2_Time_19 "2级过流时间过长告警的时间阈值(时间超过N2)(预留)";
CM_ SG_ 2417028691 S2P_Lmt8_OverCLongThanN3_Time_19 "3级过流时间过长告警的时间阈值(时间超过N3)(预留)";
CM_ SG_ 2417028692 S2P_Lmt8_OverCLongThanN1_Time_20 "1级过流时间过长告警的时间阈值(时间超过N1)(预留)";
CM_ SG_ 2417028692 S2P_Lmt8_OverCLongThanN2_Time_20 "2级过流时间过长告警的时间阈值(时间超过N2)(预留)";
CM_ SG_ 2417028692 S2P_Lmt8_OverCLongThanN3_Time_20 "3级过流时间过长告警的时间阈值(时间超过N3)(预留)";
CM_ SG_ 2417028693 S2P_Lmt8_OverCLongThanN1_Time_21 "1级过流时间过长告警的时间阈值(时间超过N1)(预留)";
CM_ SG_ 2417028693 S2P_Lmt8_OverCLongThanN2_Time_21 "2级过流时间过长告警的时间阈值(时间超过N2)(预留)";
CM_ SG_ 2417028693 S2P_Lmt8_OverCLongThanN3_Time_21 "3级过流时间过长告警的时间阈值(时间超过N3)(预留)";
CM_ SG_ 2417028694 S2P_Lmt8_OverCLongThanN1_Time_22 "1级过流时间过长告警的时间阈值(时间超过N1)(预留)";
CM_ SG_ 2417028694 S2P_Lmt8_OverCLongThanN2_Time_22 "2级过流时间过长告警的时间阈值(时间超过N2)(预留)";
CM_ SG_ 2417028694 S2P_Lmt8_OverCLongThanN3_Time_22 "3级过流时间过长告警的时间阈值(时间超过N3)(预留)";
CM_ SG_ 2417028695 S2P_Lmt8_OverCLongThanN1_Time_23 "1级过流时间过长告警的时间阈值(时间超过N1)(预留)";
CM_ SG_ 2417028695 S2P_Lmt8_OverCLongThanN2_Time_23 "2级过流时间过长告警的时间阈值(时间超过N2)(预留)";
CM_ SG_ 2417028695 S2P_Lmt8_OverCLongThanN3_Time_23 "3级过流时间过长告警的时间阈值(时间超过N3)(预留)";
CM_ SG_ 2417028696 S2P_Lmt8_OverCLongThanN1_Time_24 "1级过流时间过长告警的时间阈值(时间超过N1)(预留)";
CM_ SG_ 2417028696 S2P_Lmt8_OverCLongThanN2_Time_24 "2级过流时间过长告警的时间阈值(时间超过N2)(预留)";
CM_ SG_ 2417028696 S2P_Lmt8_OverCLongThanN3_Time_24 "3级过流时间过长告警的时间阈值(时间超过N3)(预留)";
CM_ SG_ 2417028697 S2P_Lmt8_OverCLongThanN1_Time_25 "1级过流时间过长告警的时间阈值(时间超过N1)(预留)";
CM_ SG_ 2417028697 S2P_Lmt8_OverCLongThanN2_Time_25 "2级过流时间过长告警的时间阈值(时间超过N2)(预留)";
CM_ SG_ 2417028697 S2P_Lmt8_OverCLongThanN3_Time_25 "3级过流时间过长告警的时间阈值(时间超过N3)(预留)";
CM_ SG_ 2417028698 S2P_Lmt8_OverCLongThanN1_Time_26 "1级过流时间过长告警的时间阈值(时间超过N1)(预留)";
CM_ SG_ 2417028698 S2P_Lmt8_OverCLongThanN2_Time_26 "2级过流时间过长告警的时间阈值(时间超过N2)(预留)";
CM_ SG_ 2417028698 S2P_Lmt8_OverCLongThanN3_Time_26 "3级过流时间过长告警的时间阈值(时间超过N3)(预留)";
CM_ SG_ 2417028699 S2P_Lmt8_OverCLongThanN1_Time_27 "1级过流时间过长告警的时间阈值(时间超过N1)(预留)";
CM_ SG_ 2417028699 S2P_Lmt8_OverCLongThanN2_Time_27 "2级过流时间过长告警的时间阈值(时间超过N2)(预留)";
CM_ SG_ 2417028699 S2P_Lmt8_OverCLongThanN3_Time_27 "3级过流时间过长告警的时间阈值(时间超过N3)(预留)";
CM_ SG_ 2417028700 S2P_Lmt8_OverCLongThanN1_Time_28 "1级过流时间过长告警的时间阈值(时间超过N1)(预留)";
CM_ SG_ 2417028700 S2P_Lmt8_OverCLongThanN2_Time_28 "2级过流时间过长告警的时间阈值(时间超过N2)(预留)";
CM_ SG_ 2417028700 S2P_Lmt8_OverCLongThanN3_Time_28 "3级过流时间过长告警的时间阈值(时间超过N3)(预留)";
CM_ SG_ 2417028701 S2P_Lmt8_OverCLongThanN1_Time_29 "1级过流时间过长告警的时间阈值(时间超过N1)(预留)";
CM_ SG_ 2417028701 S2P_Lmt8_OverCLongThanN2_Time_29 "2级过流时间过长告警的时间阈值(时间超过N2)(预留)";
CM_ SG_ 2417028701 S2P_Lmt8_OverCLongThanN3_Time_29 "3级过流时间过长告警的时间阈值(时间超过N3)(预留)";
CM_ SG_ 2417028702 S2P_Lmt8_OverCLongThanN1_Time_30 "1级过流时间过长告警的时间阈值(时间超过N1)(预留)";
CM_ SG_ 2417028702 S2P_Lmt8_OverCLongThanN2_Time_30 "2级过流时间过长告警的时间阈值(时间超过N2)(预留)";
CM_ SG_ 2417028702 S2P_Lmt8_OverCLongThanN3_Time_30 "3级过流时间过长告警的时间阈值(时间超过N3)(预留)";
CM_ SG_ 2417028703 S2P_Lmt8_OverCLongThanN1_Time_31 "1级过流时间过长告警的时间阈值(时间超过N1)(预留)";
CM_ SG_ 2417028703 S2P_Lmt8_OverCLongThanN2_Time_31 "2级过流时间过长告警的时间阈值(时间超过N2)(预留)";
CM_ SG_ 2417028703 S2P_Lmt8_OverCLongThanN3_Time_31 "3级过流时间过长告警的时间阈值(时间超过N3)(预留)";
CM_ SG_ 2417028704 S2P_Lmt8_OverCLongThanN1_Time_32 "1级过流时间过长告警的时间阈值(时间超过N1)(预留)";
CM_ SG_ 2417028704 S2P_Lmt8_OverCLongThanN2_Time_32 "2级过流时间过长告警的时间阈值(时间超过N2)(预留)";
CM_ SG_ 2417028704 S2P_Lmt8_OverCLongThanN3_Time_32 "3级过流时间过长告警的时间阈值(时间超过N3)(预留)";
CM_ SG_ 2417028705 S2P_Lmt8_OverCLongThanN1_Time_33 "1级过流时间过长告警的时间阈值(时间超过N1)(预留)";
CM_ SG_ 2417028705 S2P_Lmt8_OverCLongThanN2_Time_33 "2级过流时间过长告警的时间阈值(时间超过N2)(预留)";
CM_ SG_ 2417028705 S2P_Lmt8_OverCLongThanN3_Time_33 "3级过流时间过长告警的时间阈值(时间超过N3)(预留)";
CM_ SG_ 2417028706 S2P_Lmt8_OverCLongThanN1_Time_34 "1级过流时间过长告警的时间阈值(时间超过N1)(预留)";
CM_ SG_ 2417028706 S2P_Lmt8_OverCLongThanN2_Time_34 "2级过流时间过长告警的时间阈值(时间超过N2)(预留)";
CM_ SG_ 2417028706 S2P_Lmt8_OverCLongThanN3_Time_34 "3级过流时间过长告警的时间阈值(时间超过N3)(预留)";
CM_ SG_ 2417028707 S2P_Lmt8_OverCLongThanN1_Time_35 "1级过流时间过长告警的时间阈值(时间超过N1)(预留)";
CM_ SG_ 2417028707 S2P_Lmt8_OverCLongThanN2_Time_35 "2级过流时间过长告警的时间阈值(时间超过N2)(预留)";
CM_ SG_ 2417028707 S2P_Lmt8_OverCLongThanN3_Time_35 "3级过流时间过长告警的时间阈值(时间超过N3)(预留)";
CM_ SG_ 2417028708 S2P_Lmt8_OverCLongThanN1_Time_36 "1级过流时间过长告警的时间阈值(时间超过N1)(预留)";
CM_ SG_ 2417028708 S2P_Lmt8_OverCLongThanN2_Time_36 "2级过流时间过长告警的时间阈值(时间超过N2)(预留)";
CM_ SG_ 2417028708 S2P_Lmt8_OverCLongThanN3_Time_36 "3级过流时间过长告警的时间阈值(时间超过N3)(预留)";
CM_ SG_ 2417028709 S2P_Lmt8_OverCLongThanN1_Time_37 "1级过流时间过长告警的时间阈值(时间超过N1)(预留)";
CM_ SG_ 2417028709 S2P_Lmt8_OverCLongThanN2_Time_37 "2级过流时间过长告警的时间阈值(时间超过N2)(预留)";
CM_ SG_ 2417028709 S2P_Lmt8_OverCLongThanN3_Time_37 "3级过流时间过长告警的时间阈值(时间超过N3)(预留)";
CM_ SG_ 2417028710 S2P_Lmt8_OverCLongThanN1_Time_38 "1级过流时间过长告警的时间阈值(时间超过N1)(预留)";
CM_ SG_ 2417028710 S2P_Lmt8_OverCLongThanN2_Time_38 "2级过流时间过长告警的时间阈值(时间超过N2)(预留)";
CM_ SG_ 2417028710 S2P_Lmt8_OverCLongThanN3_Time_38 "3级过流时间过长告警的时间阈值(时间超过N3)(预留)";
CM_ SG_ 2417028711 S2P_Lmt8_OverCLongThanN1_Time_39 "1级过流时间过长告警的时间阈值(时间超过N1)(预留)";
CM_ SG_ 2417028711 S2P_Lmt8_OverCLongThanN2_Time_39 "2级过流时间过长告警的时间阈值(时间超过N2)(预留)";
CM_ SG_ 2417028711 S2P_Lmt8_OverCLongThanN3_Time_39 "3级过流时间过长告警的时间阈值(时间超过N3)(预留)";
CM_ SG_ 2417028712 S2P_Lmt8_OverCLongThanN1_Time_40 "1级过流时间过长告警的时间阈值(时间超过N1)(预留)";
CM_ SG_ 2417028712 S2P_Lmt8_OverCLongThanN2_Time_40 "2级过流时间过长告警的时间阈值(时间超过N2)(预留)";
CM_ SG_ 2417028712 S2P_Lmt8_OverCLongThanN3_Time_40 "3级过流时间过长告警的时间阈值(时间超过N3)(预留)";
CM_ SG_ 2417028713 S2P_Lmt8_OverCLongThanN1_Time_41 "1级过流时间过长告警的时间阈值(时间超过N1)(预留)";
CM_ SG_ 2417028713 S2P_Lmt8_OverCLongThanN2_Time_41 "2级过流时间过长告警的时间阈值(时间超过N2)(预留)";
CM_ SG_ 2417028713 S2P_Lmt8_OverCLongThanN3_Time_41 "3级过流时间过长告警的时间阈值(时间超过N3)(预留)";
CM_ SG_ 2417028714 S2P_Lmt8_OverCLongThanN1_Time_42 "1级过流时间过长告警的时间阈值(时间超过N1)(预留)";
CM_ SG_ 2417028714 S2P_Lmt8_OverCLongThanN2_Time_42 "2级过流时间过长告警的时间阈值(时间超过N2)(预留)";
CM_ SG_ 2417028714 S2P_Lmt8_OverCLongThanN3_Time_42 "3级过流时间过长告警的时间阈值(时间超过N3)(预留)";
CM_ SG_ 2417028715 S2P_Lmt8_OverCLongThanN1_Time_43 "1级过流时间过长告警的时间阈值(时间超过N1)(预留)";
CM_ SG_ 2417028715 S2P_Lmt8_OverCLongThanN2_Time_43 "2级过流时间过长告警的时间阈值(时间超过N2)(预留)";
CM_ SG_ 2417028715 S2P_Lmt8_OverCLongThanN3_Time_43 "3级过流时间过长告警的时间阈值(时间超过N3)(预留)";
CM_ SG_ 2417028716 S2P_Lmt8_OverCLongThanN1_Time_44 "1级过流时间过长告警的时间阈值(时间超过N1)(预留)";
CM_ SG_ 2417028716 S2P_Lmt8_OverCLongThanN2_Time_44 "2级过流时间过长告警的时间阈值(时间超过N2)(预留)";
CM_ SG_ 2417028716 S2P_Lmt8_OverCLongThanN3_Time_44 "3级过流时间过长告警的时间阈值(时间超过N3)(预留)";
CM_ SG_ 2417028717 S2P_Lmt8_OverCLongThanN1_Time_45 "1级过流时间过长告警的时间阈值(时间超过N1)(预留)";
CM_ SG_ 2417028717 S2P_Lmt8_OverCLongThanN2_Time_45 "2级过流时间过长告警的时间阈值(时间超过N2)(预留)";
CM_ SG_ 2417028717 S2P_Lmt8_OverCLongThanN3_Time_45 "3级过流时间过长告警的时间阈值(时间超过N3)(预留)";
CM_ SG_ 2417028718 S2P_Lmt8_OverCLongThanN1_Time_46 "1级过流时间过长告警的时间阈值(时间超过N1)(预留)";
CM_ SG_ 2417028718 S2P_Lmt8_OverCLongThanN2_Time_46 "2级过流时间过长告警的时间阈值(时间超过N2)(预留)";
CM_ SG_ 2417028718 S2P_Lmt8_OverCLongThanN3_Time_46 "3级过流时间过长告警的时间阈值(时间超过N3)(预留)";
CM_ SG_ 2417028719 S2P_Lmt8_OverCLongThanN1_Time_47 "1级过流时间过长告警的时间阈值(时间超过N1)(预留)";
CM_ SG_ 2417028719 S2P_Lmt8_OverCLongThanN2_Time_47 "2级过流时间过长告警的时间阈值(时间超过N2)(预留)";
CM_ SG_ 2417028719 S2P_Lmt8_OverCLongThanN3_Time_47 "3级过流时间过长告警的时间阈值(时间超过N3)(预留)";
CM_ SG_ 2417028720 S2P_Lmt8_OverCLongThanN1_Time_48 "1级过流时间过长告警的时间阈值(时间超过N1)(预留)";
CM_ SG_ 2417028720 S2P_Lmt8_OverCLongThanN2_Time_48 "2级过流时间过长告警的时间阈值(时间超过N2)(预留)";
CM_ SG_ 2417028720 S2P_Lmt8_OverCLongThanN3_Time_48 "3级过流时间过长告警的时间阈值(时间超过N3)(预留)";
CM_ SG_ 2417028721 S2P_Lmt8_OverCLongThanN1_Time_49 "1级过流时间过长告警的时间阈值(时间超过N1)(预留)";
CM_ SG_ 2417028721 S2P_Lmt8_OverCLongThanN2_Time_49 "2级过流时间过长告警的时间阈值(时间超过N2)(预留)";
CM_ SG_ 2417028721 S2P_Lmt8_OverCLongThanN3_Time_49 "3级过流时间过长告警的时间阈值(时间超过N3)(预留)";
CM_ SG_ 2417028722 S2P_Lmt8_OverCLongThanN1_Time_50 "1级过流时间过长告警的时间阈值(时间超过N1)(预留)";
CM_ SG_ 2417028722 S2P_Lmt8_OverCLongThanN2_Time_50 "2级过流时间过长告警的时间阈值(时间超过N2)(预留)";
CM_ SG_ 2417028722 S2P_Lmt8_OverCLongThanN3_Time_50 "3级过流时间过长告警的时间阈值(时间超过N3)(预留)";
CM_ SG_ 2417028723 S2P_Lmt8_OverCLongThanN1_Time_51 "1级过流时间过长告警的时间阈值(时间超过N1)(预留)";
CM_ SG_ 2417028723 S2P_Lmt8_OverCLongThanN2_Time_51 "2级过流时间过长告警的时间阈值(时间超过N2)(预留)";
CM_ SG_ 2417028723 S2P_Lmt8_OverCLongThanN3_Time_51 "3级过流时间过长告警的时间阈值(时间超过N3)(预留)";
CM_ SG_ 2417028724 S2P_Lmt8_OverCLongThanN1_Time_52 "1级过流时间过长告警的时间阈值(时间超过N1)(预留)";
CM_ SG_ 2417028724 S2P_Lmt8_OverCLongThanN2_Time_52 "2级过流时间过长告警的时间阈值(时间超过N2)(预留)";
CM_ SG_ 2417028724 S2P_Lmt8_OverCLongThanN3_Time_52 "3级过流时间过长告警的时间阈值(时间超过N3)(预留)";
CM_ SG_ 2417028725 S2P_Lmt8_OverCLongThanN1_Time_53 "1级过流时间过长告警的时间阈值(时间超过N1)(预留)";
CM_ SG_ 2417028725 S2P_Lmt8_OverCLongThanN2_Time_53 "2级过流时间过长告警的时间阈值(时间超过N2)(预留)";
CM_ SG_ 2417028725 S2P_Lmt8_OverCLongThanN3_Time_53 "3级过流时间过长告警的时间阈值(时间超过N3)(预留)";
CM_ SG_ 2417028726 S2P_Lmt8_OverCLongThanN1_Time_54 "1级过流时间过长告警的时间阈值(时间超过N1)(预留)";
CM_ SG_ 2417028726 S2P_Lmt8_OverCLongThanN2_Time_54 "2级过流时间过长告警的时间阈值(时间超过N2)(预留)";
CM_ SG_ 2417028726 S2P_Lmt8_OverCLongThanN3_Time_54 "3级过流时间过长告警的时间阈值(时间超过N3)(预留)";
CM_ SG_ 2417028727 S2P_Lmt8_OverCLongThanN1_Time_55 "1级过流时间过长告警的时间阈值(时间超过N1)(预留)";
CM_ SG_ 2417028727 S2P_Lmt8_OverCLongThanN2_Time_55 "2级过流时间过长告警的时间阈值(时间超过N2)(预留)";
CM_ SG_ 2417028727 S2P_Lmt8_OverCLongThanN3_Time_55 "3级过流时间过长告警的时间阈值(时间超过N3)(预留)";
CM_ SG_ 2417028728 S2P_Lmt8_OverCLongThanN1_Time_56 "1级过流时间过长告警的时间阈值(时间超过N1)(预留)";
CM_ SG_ 2417028728 S2P_Lmt8_OverCLongThanN2_Time_56 "2级过流时间过长告警的时间阈值(时间超过N2)(预留)";
CM_ SG_ 2417028728 S2P_Lmt8_OverCLongThanN3_Time_56 "3级过流时间过长告警的时间阈值(时间超过N3)(预留)";
CM_ SG_ 2417028729 S2P_Lmt8_OverCLongThanN1_Time_57 "1级过流时间过长告警的时间阈值(时间超过N1)(预留)";
CM_ SG_ 2417028729 S2P_Lmt8_OverCLongThanN2_Time_57 "2级过流时间过长告警的时间阈值(时间超过N2)(预留)";
CM_ SG_ 2417028729 S2P_Lmt8_OverCLongThanN3_Time_57 "3级过流时间过长告警的时间阈值(时间超过N3)(预留)";
CM_ SG_ 2417028730 S2P_Lmt8_OverCLongThanN1_Time_58 "1级过流时间过长告警的时间阈值(时间超过N1)(预留)";
CM_ SG_ 2417028730 S2P_Lmt8_OverCLongThanN2_Time_58 "2级过流时间过长告警的时间阈值(时间超过N2)(预留)";
CM_ SG_ 2417028730 S2P_Lmt8_OverCLongThanN3_Time_58 "3级过流时间过长告警的时间阈值(时间超过N3)(预留)";
CM_ SG_ 2417028731 S2P_Lmt8_OverCLongThanN1_Time_59 "1级过流时间过长告警的时间阈值(时间超过N1)(预留)";
CM_ SG_ 2417028731 S2P_Lmt8_OverCLongThanN2_Time_59 "2级过流时间过长告警的时间阈值(时间超过N2)(预留)";
CM_ SG_ 2417028731 S2P_Lmt8_OverCLongThanN3_Time_59 "3级过流时间过长告警的时间阈值(时间超过N3)(预留)";
CM_ SG_ 2417028732 S2P_Lmt8_OverCLongThanN1_Time_60 "1级过流时间过长告警的时间阈值(时间超过N1)(预留)";
CM_ SG_ 2417028732 S2P_Lmt8_OverCLongThanN2_Time_60 "2级过流时间过长告警的时间阈值(时间超过N2)(预留)";
CM_ SG_ 2417028732 S2P_Lmt8_OverCLongThanN3_Time_60 "3级过流时间过长告警的时间阈值(时间超过N3)(预留)";
CM_ SG_ 2417028733 S2P_Lmt8_OverCLongThanN1_Time_61 "1级过流时间过长告警的时间阈值(时间超过N1)(预留)";
CM_ SG_ 2417028733 S2P_Lmt8_OverCLongThanN2_Time_61 "2级过流时间过长告警的时间阈值(时间超过N2)(预留)";
CM_ SG_ 2417028733 S2P_Lmt8_OverCLongThanN3_Time_61 "3级过流时间过长告警的时间阈值(时间超过N3)(预留)";
CM_ SG_ 2417028734 S2P_Lmt8_OverCLongThanN1_Time_62 "1级过流时间过长告警的时间阈值(时间超过N1)(预留)";
CM_ SG_ 2417028734 S2P_Lmt8_OverCLongThanN2_Time_62 "2级过流时间过长告警的时间阈值(时间超过N2)(预留)";
CM_ SG_ 2417028734 S2P_Lmt8_OverCLongThanN3_Time_62 "3级过流时间过长告警的时间阈值(时间超过N3)(预留)";
CM_ SG_ 2417028735 S2P_Lmt8_OverCLongThanN1_Time_63 "1级过流时间过长告警的时间阈值(时间超过N1)(预留)";
CM_ SG_ 2417028735 S2P_Lmt8_OverCLongThanN2_Time_63 "2级过流时间过长告警的时间阈值(时间超过N2)(预留)";
CM_ SG_ 2417028735 S2P_Lmt8_OverCLongThanN3_Time_63 "3级过流时间过长告警的时间阈值(时间超过N3)(预留)";
CM_ SG_ 2417094209 S2P_Lmt9_Over_Tcell1_01 "电池单体高温一级报警温度";
CM_ SG_ 2417094209 S2P_Lmt9_Over_DTcell1_01 "单体过温1级告警消除回差阈值";
CM_ SG_ 2417094209 S2P_Lmt9_Over_Tcell2_01 "电池单体高温二级报警温度";
CM_ SG_ 2417094209 S2P_Lmt9_Over_DTcell2_01 "单体过温2级告警消除回差阈值";
CM_ SG_ 2417094209 S2P_Lmt9_Over_Tcell3_01 "电池单体高温三级报警温度";
CM_ SG_ 2417094209 S2P_Lmt9_Over_DTcell3_01 "单体过温3级告警消除回差阈值";
CM_ SG_ 2417094210 S2P_Lmt9_Over_Tcell1_02 "电池单体高温一级报警温度";
CM_ SG_ 2417094210 S2P_Lmt9_Over_DTcell1_02 "单体过温1级告警消除回差阈值";
CM_ SG_ 2417094210 S2P_Lmt9_Over_Tcell2_02 "电池单体高温二级报警温度";
CM_ SG_ 2417094210 S2P_Lmt9_Over_DTcell2_02 "单体过温2级告警消除回差阈值";
CM_ SG_ 2417094210 S2P_Lmt9_Over_Tcell3_02 "电池单体高温三级报警温度";
CM_ SG_ 2417094210 S2P_Lmt9_Over_DTcell3_02 "单体过温3级告警消除回差阈值";
CM_ SG_ 2417094211 S2P_Lmt9_Over_Tcell1_03 "电池单体高温一级报警温度";
CM_ SG_ 2417094211 S2P_Lmt9_Over_DTcell1_03 "单体过温1级告警消除回差阈值";
CM_ SG_ 2417094211 S2P_Lmt9_Over_Tcell2_03 "电池单体高温二级报警温度";
CM_ SG_ 2417094211 S2P_Lmt9_Over_DTcell2_03 "单体过温2级告警消除回差阈值";
CM_ SG_ 2417094211 S2P_Lmt9_Over_Tcell3_03 "电池单体高温三级报警温度";
CM_ SG_ 2417094211 S2P_Lmt9_Over_DTcell3_03 "单体过温3级告警消除回差阈值";
CM_ SG_ 2417094212 S2P_Lmt9_Over_Tcell1_04 "电池单体高温一级报警温度";
CM_ SG_ 2417094212 S2P_Lmt9_Over_DTcell1_04 "单体过温1级告警消除回差阈值";
CM_ SG_ 2417094212 S2P_Lmt9_Over_Tcell2_04 "电池单体高温二级报警温度";
CM_ SG_ 2417094212 S2P_Lmt9_Over_DTcell2_04 "单体过温2级告警消除回差阈值";
CM_ SG_ 2417094212 S2P_Lmt9_Over_Tcell3_04 "电池单体高温三级报警温度";
CM_ SG_ 2417094212 S2P_Lmt9_Over_DTcell3_04 "单体过温3级告警消除回差阈值";
CM_ SG_ 2417094213 S2P_Lmt9_Over_Tcell1_05 "电池单体高温一级报警温度";
CM_ SG_ 2417094213 S2P_Lmt9_Over_DTcell1_05 "单体过温1级告警消除回差阈值";
CM_ SG_ 2417094213 S2P_Lmt9_Over_Tcell2_05 "电池单体高温二级报警温度";
CM_ SG_ 2417094213 S2P_Lmt9_Over_DTcell2_05 "单体过温2级告警消除回差阈值";
CM_ SG_ 2417094213 S2P_Lmt9_Over_Tcell3_05 "电池单体高温三级报警温度";
CM_ SG_ 2417094213 S2P_Lmt9_Over_DTcell3_05 "单体过温3级告警消除回差阈值";
CM_ SG_ 2417094214 S2P_Lmt9_Over_Tcell1_06 "电池单体高温一级报警温度";
CM_ SG_ 2417094214 S2P_Lmt9_Over_DTcell1_06 "单体过温1级告警消除回差阈值";
CM_ SG_ 2417094214 S2P_Lmt9_Over_Tcell2_06 "电池单体高温二级报警温度";
CM_ SG_ 2417094214 S2P_Lmt9_Over_DTcell2_06 "单体过温2级告警消除回差阈值";
CM_ SG_ 2417094214 S2P_Lmt9_Over_Tcell3_06 "电池单体高温三级报警温度";
CM_ SG_ 2417094214 S2P_Lmt9_Over_DTcell3_06 "单体过温3级告警消除回差阈值";
CM_ SG_ 2417094215 S2P_Lmt9_Over_Tcell1_07 "电池单体高温一级报警温度";
CM_ SG_ 2417094215 S2P_Lmt9_Over_DTcell1_07 "单体过温1级告警消除回差阈值";
CM_ SG_ 2417094215 S2P_Lmt9_Over_Tcell2_07 "电池单体高温二级报警温度";
CM_ SG_ 2417094215 S2P_Lmt9_Over_DTcell2_07 "单体过温2级告警消除回差阈值";
CM_ SG_ 2417094215 S2P_Lmt9_Over_Tcell3_07 "电池单体高温三级报警温度";
CM_ SG_ 2417094215 S2P_Lmt9_Over_DTcell3_07 "单体过温3级告警消除回差阈值";
CM_ SG_ 2417094216 S2P_Lmt9_Over_Tcell1_08 "电池单体高温一级报警温度";
CM_ SG_ 2417094216 S2P_Lmt9_Over_DTcell1_08 "单体过温1级告警消除回差阈值";
CM_ SG_ 2417094216 S2P_Lmt9_Over_Tcell2_08 "电池单体高温二级报警温度";
CM_ SG_ 2417094216 S2P_Lmt9_Over_DTcell2_08 "单体过温2级告警消除回差阈值";
CM_ SG_ 2417094216 S2P_Lmt9_Over_Tcell3_08 "电池单体高温三级报警温度";
CM_ SG_ 2417094216 S2P_Lmt9_Over_DTcell3_08 "单体过温3级告警消除回差阈值";
CM_ SG_ 2417094217 S2P_Lmt9_Over_Tcell1_09 "电池单体高温一级报警温度";
CM_ SG_ 2417094217 S2P_Lmt9_Over_DTcell1_09 "单体过温1级告警消除回差阈值";
CM_ SG_ 2417094217 S2P_Lmt9_Over_Tcell2_09 "电池单体高温二级报警温度";
CM_ SG_ 2417094217 S2P_Lmt9_Over_DTcell2_09 "单体过温2级告警消除回差阈值";
CM_ SG_ 2417094217 S2P_Lmt9_Over_Tcell3_09 "电池单体高温三级报警温度";
CM_ SG_ 2417094217 S2P_Lmt9_Over_DTcell3_09 "单体过温3级告警消除回差阈值";
CM_ SG_ 2417094218 S2P_Lmt9_Over_Tcell1_10 "电池单体高温一级报警温度";
CM_ SG_ 2417094218 S2P_Lmt9_Over_DTcell1_10 "单体过温1级告警消除回差阈值";
CM_ SG_ 2417094218 S2P_Lmt9_Over_Tcell2_10 "电池单体高温二级报警温度";
CM_ SG_ 2417094218 S2P_Lmt9_Over_DTcell2_10 "单体过温2级告警消除回差阈值";
CM_ SG_ 2417094218 S2P_Lmt9_Over_Tcell3_10 "电池单体高温三级报警温度";
CM_ SG_ 2417094218 S2P_Lmt9_Over_DTcell3_10 "单体过温3级告警消除回差阈值";
CM_ SG_ 2417094219 S2P_Lmt9_Over_Tcell1_11 "电池单体高温一级报警温度";
CM_ SG_ 2417094219 S2P_Lmt9_Over_DTcell1_11 "单体过温1级告警消除回差阈值";
CM_ SG_ 2417094219 S2P_Lmt9_Over_Tcell2_11 "电池单体高温二级报警温度";
CM_ SG_ 2417094219 S2P_Lmt9_Over_DTcell2_11 "单体过温2级告警消除回差阈值";
CM_ SG_ 2417094219 S2P_Lmt9_Over_Tcell3_11 "电池单体高温三级报警温度";
CM_ SG_ 2417094219 S2P_Lmt9_Over_DTcell3_11 "单体过温3级告警消除回差阈值";
CM_ SG_ 2417094220 S2P_Lmt9_Over_Tcell1_12 "电池单体高温一级报警温度";
CM_ SG_ 2417094220 S2P_Lmt9_Over_DTcell1_12 "单体过温1级告警消除回差阈值";
CM_ SG_ 2417094220 S2P_Lmt9_Over_Tcell2_12 "电池单体高温二级报警温度";
CM_ SG_ 2417094220 S2P_Lmt9_Over_DTcell2_12 "单体过温2级告警消除回差阈值";
CM_ SG_ 2417094220 S2P_Lmt9_Over_Tcell3_12 "电池单体高温三级报警温度";
CM_ SG_ 2417094220 S2P_Lmt9_Over_DTcell3_12 "单体过温3级告警消除回差阈值";
CM_ SG_ 2417094221 S2P_Lmt9_Over_Tcell1_13 "电池单体高温一级报警温度";
CM_ SG_ 2417094221 S2P_Lmt9_Over_DTcell1_13 "单体过温1级告警消除回差阈值";
CM_ SG_ 2417094221 S2P_Lmt9_Over_Tcell2_13 "电池单体高温二级报警温度";
CM_ SG_ 2417094221 S2P_Lmt9_Over_DTcell2_13 "单体过温2级告警消除回差阈值";
CM_ SG_ 2417094221 S2P_Lmt9_Over_Tcell3_13 "电池单体高温三级报警温度";
CM_ SG_ 2417094221 S2P_Lmt9_Over_DTcell3_13 "单体过温3级告警消除回差阈值";
CM_ SG_ 2417094222 S2P_Lmt9_Over_Tcell1_14 "电池单体高温一级报警温度";
CM_ SG_ 2417094222 S2P_Lmt9_Over_DTcell1_14 "单体过温1级告警消除回差阈值";
CM_ SG_ 2417094222 S2P_Lmt9_Over_Tcell2_14 "电池单体高温二级报警温度";
CM_ SG_ 2417094222 S2P_Lmt9_Over_DTcell2_14 "单体过温2级告警消除回差阈值";
CM_ SG_ 2417094222 S2P_Lmt9_Over_Tcell3_14 "电池单体高温三级报警温度";
CM_ SG_ 2417094222 S2P_Lmt9_Over_DTcell3_14 "单体过温3级告警消除回差阈值";
CM_ SG_ 2417094223 S2P_Lmt9_Over_Tcell1_15 "电池单体高温一级报警温度";
CM_ SG_ 2417094223 S2P_Lmt9_Over_DTcell1_15 "单体过温1级告警消除回差阈值";
CM_ SG_ 2417094223 S2P_Lmt9_Over_Tcell2_15 "电池单体高温二级报警温度";
CM_ SG_ 2417094223 S2P_Lmt9_Over_DTcell2_15 "单体过温2级告警消除回差阈值";
CM_ SG_ 2417094223 S2P_Lmt9_Over_Tcell3_15 "电池单体高温三级报警温度";
CM_ SG_ 2417094223 S2P_Lmt9_Over_DTcell3_15 "单体过温3级告警消除回差阈值";
CM_ SG_ 2417094224 S2P_Lmt9_Over_Tcell1_16 "电池单体高温一级报警温度";
CM_ SG_ 2417094224 S2P_Lmt9_Over_DTcell1_16 "单体过温1级告警消除回差阈值";
CM_ SG_ 2417094224 S2P_Lmt9_Over_Tcell2_16 "电池单体高温二级报警温度";
CM_ SG_ 2417094224 S2P_Lmt9_Over_DTcell2_16 "单体过温2级告警消除回差阈值";
CM_ SG_ 2417094224 S2P_Lmt9_Over_Tcell3_16 "电池单体高温三级报警温度";
CM_ SG_ 2417094224 S2P_Lmt9_Over_DTcell3_16 "单体过温3级告警消除回差阈值";
CM_ SG_ 2417094225 S2P_Lmt9_Over_Tcell1_17 "电池单体高温一级报警温度";
CM_ SG_ 2417094225 S2P_Lmt9_Over_DTcell1_17 "单体过温1级告警消除回差阈值";
CM_ SG_ 2417094225 S2P_Lmt9_Over_Tcell2_17 "电池单体高温二级报警温度";
CM_ SG_ 2417094225 S2P_Lmt9_Over_DTcell2_17 "单体过温2级告警消除回差阈值";
CM_ SG_ 2417094225 S2P_Lmt9_Over_Tcell3_17 "电池单体高温三级报警温度";
CM_ SG_ 2417094225 S2P_Lmt9_Over_DTcell3_17 "单体过温3级告警消除回差阈值";
CM_ SG_ 2417094226 S2P_Lmt9_Over_Tcell1_18 "电池单体高温一级报警温度";
CM_ SG_ 2417094226 S2P_Lmt9_Over_DTcell1_18 "单体过温1级告警消除回差阈值";
CM_ SG_ 2417094226 S2P_Lmt9_Over_Tcell2_18 "电池单体高温二级报警温度";
CM_ SG_ 2417094226 S2P_Lmt9_Over_DTcell2_18 "单体过温2级告警消除回差阈值";
CM_ SG_ 2417094226 S2P_Lmt9_Over_Tcell3_18 "电池单体高温三级报警温度";
CM_ SG_ 2417094226 S2P_Lmt9_Over_DTcell3_18 "单体过温3级告警消除回差阈值";
CM_ SG_ 2417094227 S2P_Lmt9_Over_Tcell1_19 "电池单体高温一级报警温度";
CM_ SG_ 2417094227 S2P_Lmt9_Over_DTcell1_19 "单体过温1级告警消除回差阈值";
CM_ SG_ 2417094227 S2P_Lmt9_Over_Tcell2_19 "电池单体高温二级报警温度";
CM_ SG_ 2417094227 S2P_Lmt9_Over_DTcell2_19 "单体过温2级告警消除回差阈值";
CM_ SG_ 2417094227 S2P_Lmt9_Over_Tcell3_19 "电池单体高温三级报警温度";
CM_ SG_ 2417094227 S2P_Lmt9_Over_DTcell3_19 "单体过温3级告警消除回差阈值";
CM_ SG_ 2417094228 S2P_Lmt9_Over_Tcell1_20 "电池单体高温一级报警温度";
CM_ SG_ 2417094228 S2P_Lmt9_Over_DTcell1_20 "单体过温1级告警消除回差阈值";
CM_ SG_ 2417094228 S2P_Lmt9_Over_Tcell2_20 "电池单体高温二级报警温度";
CM_ SG_ 2417094228 S2P_Lmt9_Over_DTcell2_20 "单体过温2级告警消除回差阈值";
CM_ SG_ 2417094228 S2P_Lmt9_Over_Tcell3_20 "电池单体高温三级报警温度";
CM_ SG_ 2417094228 S2P_Lmt9_Over_DTcell3_20 "单体过温3级告警消除回差阈值";
CM_ SG_ 2417094229 S2P_Lmt9_Over_Tcell1_21 "电池单体高温一级报警温度";
CM_ SG_ 2417094229 S2P_Lmt9_Over_DTcell1_21 "单体过温1级告警消除回差阈值";
CM_ SG_ 2417094229 S2P_Lmt9_Over_Tcell2_21 "电池单体高温二级报警温度";
CM_ SG_ 2417094229 S2P_Lmt9_Over_DTcell2_21 "单体过温2级告警消除回差阈值";
CM_ SG_ 2417094229 S2P_Lmt9_Over_Tcell3_21 "电池单体高温三级报警温度";
CM_ SG_ 2417094229 S2P_Lmt9_Over_DTcell3_21 "单体过温3级告警消除回差阈值";
CM_ SG_ 2417094230 S2P_Lmt9_Over_Tcell1_22 "电池单体高温一级报警温度";
CM_ SG_ 2417094230 S2P_Lmt9_Over_DTcell1_22 "单体过温1级告警消除回差阈值";
CM_ SG_ 2417094230 S2P_Lmt9_Over_Tcell2_22 "电池单体高温二级报警温度";
CM_ SG_ 2417094230 S2P_Lmt9_Over_DTcell2_22 "单体过温2级告警消除回差阈值";
CM_ SG_ 2417094230 S2P_Lmt9_Over_Tcell3_22 "电池单体高温三级报警温度";
CM_ SG_ 2417094230 S2P_Lmt9_Over_DTcell3_22 "单体过温3级告警消除回差阈值";
CM_ SG_ 2417094231 S2P_Lmt9_Over_Tcell1_23 "电池单体高温一级报警温度";
CM_ SG_ 2417094231 S2P_Lmt9_Over_DTcell1_23 "单体过温1级告警消除回差阈值";
CM_ SG_ 2417094231 S2P_Lmt9_Over_Tcell2_23 "电池单体高温二级报警温度";
CM_ SG_ 2417094231 S2P_Lmt9_Over_DTcell2_23 "单体过温2级告警消除回差阈值";
CM_ SG_ 2417094231 S2P_Lmt9_Over_Tcell3_23 "电池单体高温三级报警温度";
CM_ SG_ 2417094231 S2P_Lmt9_Over_DTcell3_23 "单体过温3级告警消除回差阈值";
CM_ SG_ 2417094232 S2P_Lmt9_Over_Tcell1_24 "电池单体高温一级报警温度";
CM_ SG_ 2417094232 S2P_Lmt9_Over_DTcell1_24 "单体过温1级告警消除回差阈值";
CM_ SG_ 2417094232 S2P_Lmt9_Over_Tcell2_24 "电池单体高温二级报警温度";
CM_ SG_ 2417094232 S2P_Lmt9_Over_DTcell2_24 "单体过温2级告警消除回差阈值";
CM_ SG_ 2417094232 S2P_Lmt9_Over_Tcell3_24 "电池单体高温三级报警温度";
CM_ SG_ 2417094232 S2P_Lmt9_Over_DTcell3_24 "单体过温3级告警消除回差阈值";
CM_ SG_ 2417094233 S2P_Lmt9_Over_Tcell1_25 "电池单体高温一级报警温度";
CM_ SG_ 2417094233 S2P_Lmt9_Over_DTcell1_25 "单体过温1级告警消除回差阈值";
CM_ SG_ 2417094233 S2P_Lmt9_Over_Tcell2_25 "电池单体高温二级报警温度";
CM_ SG_ 2417094233 S2P_Lmt9_Over_DTcell2_25 "单体过温2级告警消除回差阈值";
CM_ SG_ 2417094233 S2P_Lmt9_Over_Tcell3_25 "电池单体高温三级报警温度";
CM_ SG_ 2417094233 S2P_Lmt9_Over_DTcell3_25 "单体过温3级告警消除回差阈值";
CM_ SG_ 2417094234 S2P_Lmt9_Over_Tcell1_26 "电池单体高温一级报警温度";
CM_ SG_ 2417094234 S2P_Lmt9_Over_DTcell1_26 "单体过温1级告警消除回差阈值";
CM_ SG_ 2417094234 S2P_Lmt9_Over_Tcell2_26 "电池单体高温二级报警温度";
CM_ SG_ 2417094234 S2P_Lmt9_Over_DTcell2_26 "单体过温2级告警消除回差阈值";
CM_ SG_ 2417094234 S2P_Lmt9_Over_Tcell3_26 "电池单体高温三级报警温度";
CM_ SG_ 2417094234 S2P_Lmt9_Over_DTcell3_26 "单体过温3级告警消除回差阈值";
CM_ SG_ 2417094235 S2P_Lmt9_Over_Tcell1_27 "电池单体高温一级报警温度";
CM_ SG_ 2417094235 S2P_Lmt9_Over_DTcell1_27 "单体过温1级告警消除回差阈值";
CM_ SG_ 2417094235 S2P_Lmt9_Over_Tcell2_27 "电池单体高温二级报警温度";
CM_ SG_ 2417094235 S2P_Lmt9_Over_DTcell2_27 "单体过温2级告警消除回差阈值";
CM_ SG_ 2417094235 S2P_Lmt9_Over_Tcell3_27 "电池单体高温三级报警温度";
CM_ SG_ 2417094235 S2P_Lmt9_Over_DTcell3_27 "单体过温3级告警消除回差阈值";
CM_ SG_ 2417094236 S2P_Lmt9_Over_Tcell1_28 "电池单体高温一级报警温度";
CM_ SG_ 2417094236 S2P_Lmt9_Over_DTcell1_28 "单体过温1级告警消除回差阈值";
CM_ SG_ 2417094236 S2P_Lmt9_Over_Tcell2_28 "电池单体高温二级报警温度";
CM_ SG_ 2417094236 S2P_Lmt9_Over_DTcell2_28 "单体过温2级告警消除回差阈值";
CM_ SG_ 2417094236 S2P_Lmt9_Over_Tcell3_28 "电池单体高温三级报警温度";
CM_ SG_ 2417094236 S2P_Lmt9_Over_DTcell3_28 "单体过温3级告警消除回差阈值";
CM_ SG_ 2417094237 S2P_Lmt9_Over_Tcell1_29 "电池单体高温一级报警温度";
CM_ SG_ 2417094237 S2P_Lmt9_Over_DTcell1_29 "单体过温1级告警消除回差阈值";
CM_ SG_ 2417094237 S2P_Lmt9_Over_Tcell2_29 "电池单体高温二级报警温度";
CM_ SG_ 2417094237 S2P_Lmt9_Over_DTcell2_29 "单体过温2级告警消除回差阈值";
CM_ SG_ 2417094237 S2P_Lmt9_Over_Tcell3_29 "电池单体高温三级报警温度";
CM_ SG_ 2417094237 S2P_Lmt9_Over_DTcell3_29 "单体过温3级告警消除回差阈值";
CM_ SG_ 2417094238 S2P_Lmt9_Over_Tcell1_30 "电池单体高温一级报警温度";
CM_ SG_ 2417094238 S2P_Lmt9_Over_DTcell1_30 "单体过温1级告警消除回差阈值";
CM_ SG_ 2417094238 S2P_Lmt9_Over_Tcell2_30 "电池单体高温二级报警温度";
CM_ SG_ 2417094238 S2P_Lmt9_Over_DTcell2_30 "单体过温2级告警消除回差阈值";
CM_ SG_ 2417094238 S2P_Lmt9_Over_Tcell3_30 "电池单体高温三级报警温度";
CM_ SG_ 2417094238 S2P_Lmt9_Over_DTcell3_30 "单体过温3级告警消除回差阈值";
CM_ SG_ 2417094239 S2P_Lmt9_Over_Tcell1_31 "电池单体高温一级报警温度";
CM_ SG_ 2417094239 S2P_Lmt9_Over_DTcell1_31 "单体过温1级告警消除回差阈值";
CM_ SG_ 2417094239 S2P_Lmt9_Over_Tcell2_31 "电池单体高温二级报警温度";
CM_ SG_ 2417094239 S2P_Lmt9_Over_DTcell2_31 "单体过温2级告警消除回差阈值";
CM_ SG_ 2417094239 S2P_Lmt9_Over_Tcell3_31 "电池单体高温三级报警温度";
CM_ SG_ 2417094239 S2P_Lmt9_Over_DTcell3_31 "单体过温3级告警消除回差阈值";
CM_ SG_ 2417094240 S2P_Lmt9_Over_Tcell1_32 "电池单体高温一级报警温度";
CM_ SG_ 2417094240 S2P_Lmt9_Over_DTcell1_32 "单体过温1级告警消除回差阈值";
CM_ SG_ 2417094240 S2P_Lmt9_Over_Tcell2_32 "电池单体高温二级报警温度";
CM_ SG_ 2417094240 S2P_Lmt9_Over_DTcell2_32 "单体过温2级告警消除回差阈值";
CM_ SG_ 2417094240 S2P_Lmt9_Over_Tcell3_32 "电池单体高温三级报警温度";
CM_ SG_ 2417094240 S2P_Lmt9_Over_DTcell3_32 "单体过温3级告警消除回差阈值";
CM_ SG_ 2417094241 S2P_Lmt9_Over_Tcell1_33 "电池单体高温一级报警温度";
CM_ SG_ 2417094241 S2P_Lmt9_Over_DTcell1_33 "单体过温1级告警消除回差阈值";
CM_ SG_ 2417094241 S2P_Lmt9_Over_Tcell2_33 "电池单体高温二级报警温度";
CM_ SG_ 2417094241 S2P_Lmt9_Over_DTcell2_33 "单体过温2级告警消除回差阈值";
CM_ SG_ 2417094241 S2P_Lmt9_Over_Tcell3_33 "电池单体高温三级报警温度";
CM_ SG_ 2417094241 S2P_Lmt9_Over_DTcell3_33 "单体过温3级告警消除回差阈值";
CM_ SG_ 2417094242 S2P_Lmt9_Over_Tcell1_34 "电池单体高温一级报警温度";
CM_ SG_ 2417094242 S2P_Lmt9_Over_DTcell1_34 "单体过温1级告警消除回差阈值";
CM_ SG_ 2417094242 S2P_Lmt9_Over_Tcell2_34 "电池单体高温二级报警温度";
CM_ SG_ 2417094242 S2P_Lmt9_Over_DTcell2_34 "单体过温2级告警消除回差阈值";
CM_ SG_ 2417094242 S2P_Lmt9_Over_Tcell3_34 "电池单体高温三级报警温度";
CM_ SG_ 2417094242 S2P_Lmt9_Over_DTcell3_34 "单体过温3级告警消除回差阈值";
CM_ SG_ 2417094243 S2P_Lmt9_Over_Tcell1_35 "电池单体高温一级报警温度";
CM_ SG_ 2417094243 S2P_Lmt9_Over_DTcell1_35 "单体过温1级告警消除回差阈值";
CM_ SG_ 2417094243 S2P_Lmt9_Over_Tcell2_35 "电池单体高温二级报警温度";
CM_ SG_ 2417094243 S2P_Lmt9_Over_DTcell2_35 "单体过温2级告警消除回差阈值";
CM_ SG_ 2417094243 S2P_Lmt9_Over_Tcell3_35 "电池单体高温三级报警温度";
CM_ SG_ 2417094243 S2P_Lmt9_Over_DTcell3_35 "单体过温3级告警消除回差阈值";
CM_ SG_ 2417094244 S2P_Lmt9_Over_Tcell1_36 "电池单体高温一级报警温度";
CM_ SG_ 2417094244 S2P_Lmt9_Over_DTcell1_36 "单体过温1级告警消除回差阈值";
CM_ SG_ 2417094244 S2P_Lmt9_Over_Tcell2_36 "电池单体高温二级报警温度";
CM_ SG_ 2417094244 S2P_Lmt9_Over_DTcell2_36 "单体过温2级告警消除回差阈值";
CM_ SG_ 2417094244 S2P_Lmt9_Over_Tcell3_36 "电池单体高温三级报警温度";
CM_ SG_ 2417094244 S2P_Lmt9_Over_DTcell3_36 "单体过温3级告警消除回差阈值";
CM_ SG_ 2417094245 S2P_Lmt9_Over_Tcell1_37 "电池单体高温一级报警温度";
CM_ SG_ 2417094245 S2P_Lmt9_Over_DTcell1_37 "单体过温1级告警消除回差阈值";
CM_ SG_ 2417094245 S2P_Lmt9_Over_Tcell2_37 "电池单体高温二级报警温度";
CM_ SG_ 2417094245 S2P_Lmt9_Over_DTcell2_37 "单体过温2级告警消除回差阈值";
CM_ SG_ 2417094245 S2P_Lmt9_Over_Tcell3_37 "电池单体高温三级报警温度";
CM_ SG_ 2417094245 S2P_Lmt9_Over_DTcell3_37 "单体过温3级告警消除回差阈值";
CM_ SG_ 2417094246 S2P_Lmt9_Over_Tcell1_38 "电池单体高温一级报警温度";
CM_ SG_ 2417094246 S2P_Lmt9_Over_DTcell1_38 "单体过温1级告警消除回差阈值";
CM_ SG_ 2417094246 S2P_Lmt9_Over_Tcell2_38 "电池单体高温二级报警温度";
CM_ SG_ 2417094246 S2P_Lmt9_Over_DTcell2_38 "单体过温2级告警消除回差阈值";
CM_ SG_ 2417094246 S2P_Lmt9_Over_Tcell3_38 "电池单体高温三级报警温度";
CM_ SG_ 2417094246 S2P_Lmt9_Over_DTcell3_38 "单体过温3级告警消除回差阈值";
CM_ SG_ 2417094247 S2P_Lmt9_Over_Tcell1_39 "电池单体高温一级报警温度";
CM_ SG_ 2417094247 S2P_Lmt9_Over_DTcell1_39 "单体过温1级告警消除回差阈值";
CM_ SG_ 2417094247 S2P_Lmt9_Over_Tcell2_39 "电池单体高温二级报警温度";
CM_ SG_ 2417094247 S2P_Lmt9_Over_DTcell2_39 "单体过温2级告警消除回差阈值";
CM_ SG_ 2417094247 S2P_Lmt9_Over_Tcell3_39 "电池单体高温三级报警温度";
CM_ SG_ 2417094247 S2P_Lmt9_Over_DTcell3_39 "单体过温3级告警消除回差阈值";
CM_ SG_ 2417094248 S2P_Lmt9_Over_Tcell1_40 "电池单体高温一级报警温度";
CM_ SG_ 2417094248 S2P_Lmt9_Over_DTcell1_40 "单体过温1级告警消除回差阈值";
CM_ SG_ 2417094248 S2P_Lmt9_Over_Tcell2_40 "电池单体高温二级报警温度";
CM_ SG_ 2417094248 S2P_Lmt9_Over_DTcell2_40 "单体过温2级告警消除回差阈值";
CM_ SG_ 2417094248 S2P_Lmt9_Over_Tcell3_40 "电池单体高温三级报警温度";
CM_ SG_ 2417094248 S2P_Lmt9_Over_DTcell3_40 "单体过温3级告警消除回差阈值";
CM_ SG_ 2417094249 S2P_Lmt9_Over_Tcell1_41 "电池单体高温一级报警温度";
CM_ SG_ 2417094249 S2P_Lmt9_Over_DTcell1_41 "单体过温1级告警消除回差阈值";
CM_ SG_ 2417094249 S2P_Lmt9_Over_Tcell2_41 "电池单体高温二级报警温度";
CM_ SG_ 2417094249 S2P_Lmt9_Over_DTcell2_41 "单体过温2级告警消除回差阈值";
CM_ SG_ 2417094249 S2P_Lmt9_Over_Tcell3_41 "电池单体高温三级报警温度";
CM_ SG_ 2417094249 S2P_Lmt9_Over_DTcell3_41 "单体过温3级告警消除回差阈值";
CM_ SG_ 2417094250 S2P_Lmt9_Over_Tcell1_42 "电池单体高温一级报警温度";
CM_ SG_ 2417094250 S2P_Lmt9_Over_DTcell1_42 "单体过温1级告警消除回差阈值";
CM_ SG_ 2417094250 S2P_Lmt9_Over_Tcell2_42 "电池单体高温二级报警温度";
CM_ SG_ 2417094250 S2P_Lmt9_Over_DTcell2_42 "单体过温2级告警消除回差阈值";
CM_ SG_ 2417094250 S2P_Lmt9_Over_Tcell3_42 "电池单体高温三级报警温度";
CM_ SG_ 2417094250 S2P_Lmt9_Over_DTcell3_42 "单体过温3级告警消除回差阈值";
CM_ SG_ 2417094251 S2P_Lmt9_Over_Tcell1_43 "电池单体高温一级报警温度";
CM_ SG_ 2417094251 S2P_Lmt9_Over_DTcell1_43 "单体过温1级告警消除回差阈值";
CM_ SG_ 2417094251 S2P_Lmt9_Over_Tcell2_43 "电池单体高温二级报警温度";
CM_ SG_ 2417094251 S2P_Lmt9_Over_DTcell2_43 "单体过温2级告警消除回差阈值";
CM_ SG_ 2417094251 S2P_Lmt9_Over_Tcell3_43 "电池单体高温三级报警温度";
CM_ SG_ 2417094251 S2P_Lmt9_Over_DTcell3_43 "单体过温3级告警消除回差阈值";
CM_ SG_ 2417094252 S2P_Lmt9_Over_Tcell1_44 "电池单体高温一级报警温度";
CM_ SG_ 2417094252 S2P_Lmt9_Over_DTcell1_44 "单体过温1级告警消除回差阈值";
CM_ SG_ 2417094252 S2P_Lmt9_Over_Tcell2_44 "电池单体高温二级报警温度";
CM_ SG_ 2417094252 S2P_Lmt9_Over_DTcell2_44 "单体过温2级告警消除回差阈值";
CM_ SG_ 2417094252 S2P_Lmt9_Over_Tcell3_44 "电池单体高温三级报警温度";
CM_ SG_ 2417094252 S2P_Lmt9_Over_DTcell3_44 "单体过温3级告警消除回差阈值";
CM_ SG_ 2417094253 S2P_Lmt9_Over_Tcell1_45 "电池单体高温一级报警温度";
CM_ SG_ 2417094253 S2P_Lmt9_Over_DTcell1_45 "单体过温1级告警消除回差阈值";
CM_ SG_ 2417094253 S2P_Lmt9_Over_Tcell2_45 "电池单体高温二级报警温度";
CM_ SG_ 2417094253 S2P_Lmt9_Over_DTcell2_45 "单体过温2级告警消除回差阈值";
CM_ SG_ 2417094253 S2P_Lmt9_Over_Tcell3_45 "电池单体高温三级报警温度";
CM_ SG_ 2417094253 S2P_Lmt9_Over_DTcell3_45 "单体过温3级告警消除回差阈值";
CM_ SG_ 2417094254 S2P_Lmt9_Over_Tcell1_46 "电池单体高温一级报警温度";
CM_ SG_ 2417094254 S2P_Lmt9_Over_DTcell1_46 "单体过温1级告警消除回差阈值";
CM_ SG_ 2417094254 S2P_Lmt9_Over_Tcell2_46 "电池单体高温二级报警温度";
CM_ SG_ 2417094254 S2P_Lmt9_Over_DTcell2_46 "单体过温2级告警消除回差阈值";
CM_ SG_ 2417094254 S2P_Lmt9_Over_Tcell3_46 "电池单体高温三级报警温度";
CM_ SG_ 2417094254 S2P_Lmt9_Over_DTcell3_46 "单体过温3级告警消除回差阈值";
CM_ SG_ 2417094255 S2P_Lmt9_Over_Tcell1_47 "电池单体高温一级报警温度";
CM_ SG_ 2417094255 S2P_Lmt9_Over_DTcell1_47 "单体过温1级告警消除回差阈值";
CM_ SG_ 2417094255 S2P_Lmt9_Over_Tcell2_47 "电池单体高温二级报警温度";
CM_ SG_ 2417094255 S2P_Lmt9_Over_DTcell2_47 "单体过温2级告警消除回差阈值";
CM_ SG_ 2417094255 S2P_Lmt9_Over_Tcell3_47 "电池单体高温三级报警温度";
CM_ SG_ 2417094255 S2P_Lmt9_Over_DTcell3_47 "单体过温3级告警消除回差阈值";
CM_ SG_ 2417094256 S2P_Lmt9_Over_Tcell1_48 "电池单体高温一级报警温度";
CM_ SG_ 2417094256 S2P_Lmt9_Over_DTcell1_48 "单体过温1级告警消除回差阈值";
CM_ SG_ 2417094256 S2P_Lmt9_Over_Tcell2_48 "电池单体高温二级报警温度";
CM_ SG_ 2417094256 S2P_Lmt9_Over_DTcell2_48 "单体过温2级告警消除回差阈值";
CM_ SG_ 2417094256 S2P_Lmt9_Over_Tcell3_48 "电池单体高温三级报警温度";
CM_ SG_ 2417094256 S2P_Lmt9_Over_DTcell3_48 "单体过温3级告警消除回差阈值";
CM_ SG_ 2417094257 S2P_Lmt9_Over_Tcell1_49 "电池单体高温一级报警温度";
CM_ SG_ 2417094257 S2P_Lmt9_Over_DTcell1_49 "单体过温1级告警消除回差阈值";
CM_ SG_ 2417094257 S2P_Lmt9_Over_Tcell2_49 "电池单体高温二级报警温度";
CM_ SG_ 2417094257 S2P_Lmt9_Over_DTcell2_49 "单体过温2级告警消除回差阈值";
CM_ SG_ 2417094257 S2P_Lmt9_Over_Tcell3_49 "电池单体高温三级报警温度";
CM_ SG_ 2417094257 S2P_Lmt9_Over_DTcell3_49 "单体过温3级告警消除回差阈值";
CM_ SG_ 2417094258 S2P_Lmt9_Over_Tcell1_50 "电池单体高温一级报警温度";
CM_ SG_ 2417094258 S2P_Lmt9_Over_DTcell1_50 "单体过温1级告警消除回差阈值";
CM_ SG_ 2417094258 S2P_Lmt9_Over_Tcell2_50 "电池单体高温二级报警温度";
CM_ SG_ 2417094258 S2P_Lmt9_Over_DTcell2_50 "单体过温2级告警消除回差阈值";
CM_ SG_ 2417094258 S2P_Lmt9_Over_Tcell3_50 "电池单体高温三级报警温度";
CM_ SG_ 2417094258 S2P_Lmt9_Over_DTcell3_50 "单体过温3级告警消除回差阈值";
CM_ SG_ 2417094259 S2P_Lmt9_Over_Tcell1_51 "电池单体高温一级报警温度";
CM_ SG_ 2417094259 S2P_Lmt9_Over_DTcell1_51 "单体过温1级告警消除回差阈值";
CM_ SG_ 2417094259 S2P_Lmt9_Over_Tcell2_51 "电池单体高温二级报警温度";
CM_ SG_ 2417094259 S2P_Lmt9_Over_DTcell2_51 "单体过温2级告警消除回差阈值";
CM_ SG_ 2417094259 S2P_Lmt9_Over_Tcell3_51 "电池单体高温三级报警温度";
CM_ SG_ 2417094259 S2P_Lmt9_Over_DTcell3_51 "单体过温3级告警消除回差阈值";
CM_ SG_ 2417094260 S2P_Lmt9_Over_Tcell1_52 "电池单体高温一级报警温度";
CM_ SG_ 2417094260 S2P_Lmt9_Over_DTcell1_52 "单体过温1级告警消除回差阈值";
CM_ SG_ 2417094260 S2P_Lmt9_Over_Tcell2_52 "电池单体高温二级报警温度";
CM_ SG_ 2417094260 S2P_Lmt9_Over_DTcell2_52 "单体过温2级告警消除回差阈值";
CM_ SG_ 2417094260 S2P_Lmt9_Over_Tcell3_52 "电池单体高温三级报警温度";
CM_ SG_ 2417094260 S2P_Lmt9_Over_DTcell3_52 "单体过温3级告警消除回差阈值";
CM_ SG_ 2417094261 S2P_Lmt9_Over_Tcell1_53 "电池单体高温一级报警温度";
CM_ SG_ 2417094261 S2P_Lmt9_Over_DTcell1_53 "单体过温1级告警消除回差阈值";
CM_ SG_ 2417094261 S2P_Lmt9_Over_Tcell2_53 "电池单体高温二级报警温度";
CM_ SG_ 2417094261 S2P_Lmt9_Over_DTcell2_53 "单体过温2级告警消除回差阈值";
CM_ SG_ 2417094261 S2P_Lmt9_Over_Tcell3_53 "电池单体高温三级报警温度";
CM_ SG_ 2417094261 S2P_Lmt9_Over_DTcell3_53 "单体过温3级告警消除回差阈值";
CM_ SG_ 2417094262 S2P_Lmt9_Over_Tcell1_54 "电池单体高温一级报警温度";
CM_ SG_ 2417094262 S2P_Lmt9_Over_DTcell1_54 "单体过温1级告警消除回差阈值";
CM_ SG_ 2417094262 S2P_Lmt9_Over_Tcell2_54 "电池单体高温二级报警温度";
CM_ SG_ 2417094262 S2P_Lmt9_Over_DTcell2_54 "单体过温2级告警消除回差阈值";
CM_ SG_ 2417094262 S2P_Lmt9_Over_Tcell3_54 "电池单体高温三级报警温度";
CM_ SG_ 2417094262 S2P_Lmt9_Over_DTcell3_54 "单体过温3级告警消除回差阈值";
CM_ SG_ 2417094263 S2P_Lmt9_Over_Tcell1_55 "电池单体高温一级报警温度";
CM_ SG_ 2417094263 S2P_Lmt9_Over_DTcell1_55 "单体过温1级告警消除回差阈值";
CM_ SG_ 2417094263 S2P_Lmt9_Over_Tcell2_55 "电池单体高温二级报警温度";
CM_ SG_ 2417094263 S2P_Lmt9_Over_DTcell2_55 "单体过温2级告警消除回差阈值";
CM_ SG_ 2417094263 S2P_Lmt9_Over_Tcell3_55 "电池单体高温三级报警温度";
CM_ SG_ 2417094263 S2P_Lmt9_Over_DTcell3_55 "单体过温3级告警消除回差阈值";
CM_ SG_ 2417094264 S2P_Lmt9_Over_Tcell1_56 "电池单体高温一级报警温度";
CM_ SG_ 2417094264 S2P_Lmt9_Over_DTcell1_56 "单体过温1级告警消除回差阈值";
CM_ SG_ 2417094264 S2P_Lmt9_Over_Tcell2_56 "电池单体高温二级报警温度";
CM_ SG_ 2417094264 S2P_Lmt9_Over_DTcell2_56 "单体过温2级告警消除回差阈值";
CM_ SG_ 2417094264 S2P_Lmt9_Over_Tcell3_56 "电池单体高温三级报警温度";
CM_ SG_ 2417094264 S2P_Lmt9_Over_DTcell3_56 "单体过温3级告警消除回差阈值";
CM_ SG_ 2417094265 S2P_Lmt9_Over_Tcell1_57 "电池单体高温一级报警温度";
CM_ SG_ 2417094265 S2P_Lmt9_Over_DTcell1_57 "单体过温1级告警消除回差阈值";
CM_ SG_ 2417094265 S2P_Lmt9_Over_Tcell2_57 "电池单体高温二级报警温度";
CM_ SG_ 2417094265 S2P_Lmt9_Over_DTcell2_57 "单体过温2级告警消除回差阈值";
CM_ SG_ 2417094265 S2P_Lmt9_Over_Tcell3_57 "电池单体高温三级报警温度";
CM_ SG_ 2417094265 S2P_Lmt9_Over_DTcell3_57 "单体过温3级告警消除回差阈值";
CM_ SG_ 2417094266 S2P_Lmt9_Over_Tcell1_58 "电池单体高温一级报警温度";
CM_ SG_ 2417094266 S2P_Lmt9_Over_DTcell1_58 "单体过温1级告警消除回差阈值";
CM_ SG_ 2417094266 S2P_Lmt9_Over_Tcell2_58 "电池单体高温二级报警温度";
CM_ SG_ 2417094266 S2P_Lmt9_Over_DTcell2_58 "单体过温2级告警消除回差阈值";
CM_ SG_ 2417094266 S2P_Lmt9_Over_Tcell3_58 "电池单体高温三级报警温度";
CM_ SG_ 2417094266 S2P_Lmt9_Over_DTcell3_58 "单体过温3级告警消除回差阈值";
CM_ SG_ 2417094267 S2P_Lmt9_Over_Tcell1_59 "电池单体高温一级报警温度";
CM_ SG_ 2417094267 S2P_Lmt9_Over_DTcell1_59 "单体过温1级告警消除回差阈值";
CM_ SG_ 2417094267 S2P_Lmt9_Over_Tcell2_59 "电池单体高温二级报警温度";
CM_ SG_ 2417094267 S2P_Lmt9_Over_DTcell2_59 "单体过温2级告警消除回差阈值";
CM_ SG_ 2417094267 S2P_Lmt9_Over_Tcell3_59 "电池单体高温三级报警温度";
CM_ SG_ 2417094267 S2P_Lmt9_Over_DTcell3_59 "单体过温3级告警消除回差阈值";
CM_ SG_ 2417094268 S2P_Lmt9_Over_Tcell1_60 "电池单体高温一级报警温度";
CM_ SG_ 2417094268 S2P_Lmt9_Over_DTcell1_60 "单体过温1级告警消除回差阈值";
CM_ SG_ 2417094268 S2P_Lmt9_Over_Tcell2_60 "电池单体高温二级报警温度";
CM_ SG_ 2417094268 S2P_Lmt9_Over_DTcell2_60 "单体过温2级告警消除回差阈值";
CM_ SG_ 2417094268 S2P_Lmt9_Over_Tcell3_60 "电池单体高温三级报警温度";
CM_ SG_ 2417094268 S2P_Lmt9_Over_DTcell3_60 "单体过温3级告警消除回差阈值";
CM_ SG_ 2417094269 S2P_Lmt9_Over_Tcell1_61 "电池单体高温一级报警温度";
CM_ SG_ 2417094269 S2P_Lmt9_Over_DTcell1_61 "单体过温1级告警消除回差阈值";
CM_ SG_ 2417094269 S2P_Lmt9_Over_Tcell2_61 "电池单体高温二级报警温度";
CM_ SG_ 2417094269 S2P_Lmt9_Over_DTcell2_61 "单体过温2级告警消除回差阈值";
CM_ SG_ 2417094269 S2P_Lmt9_Over_Tcell3_61 "电池单体高温三级报警温度";
CM_ SG_ 2417094269 S2P_Lmt9_Over_DTcell3_61 "单体过温3级告警消除回差阈值";
CM_ SG_ 2417094270 S2P_Lmt9_Over_Tcell1_62 "电池单体高温一级报警温度";
CM_ SG_ 2417094270 S2P_Lmt9_Over_DTcell1_62 "单体过温1级告警消除回差阈值";
CM_ SG_ 2417094270 S2P_Lmt9_Over_Tcell2_62 "电池单体高温二级报警温度";
CM_ SG_ 2417094270 S2P_Lmt9_Over_DTcell2_62 "单体过温2级告警消除回差阈值";
CM_ SG_ 2417094270 S2P_Lmt9_Over_Tcell3_62 "电池单体高温三级报警温度";
CM_ SG_ 2417094270 S2P_Lmt9_Over_DTcell3_62 "单体过温3级告警消除回差阈值";
CM_ SG_ 2417094271 S2P_Lmt9_Over_Tcell1_63 "电池单体高温一级报警温度";
CM_ SG_ 2417094271 S2P_Lmt9_Over_DTcell1_63 "单体过温1级告警消除回差阈值";
CM_ SG_ 2417094271 S2P_Lmt9_Over_Tcell2_63 "电池单体高温二级报警温度";
CM_ SG_ 2417094271 S2P_Lmt9_Over_DTcell2_63 "单体过温2级告警消除回差阈值";
CM_ SG_ 2417094271 S2P_Lmt9_Over_Tcell3_63 "电池单体高温三级报警温度";
CM_ SG_ 2417094271 S2P_Lmt9_Over_DTcell3_63 "单体过温3级告警消除回差阈值";
CM_ SG_ 2417159745 S2P_Lmt10_Under_Tcell1_01 "电池单体低温一级报警温度";
CM_ SG_ 2417159745 S2P_Lmt10_Under_DTcell1_01 "单体低温1级告警消除回差阈值";
CM_ SG_ 2417159745 S2P_Lmt10_Under_Tcell2_01 "电池单体低温二级报警温度";
CM_ SG_ 2417159745 S2P_Lmt10_Under_DTcell2_01 "单体低温2级告警消除回差阈值";
CM_ SG_ 2417159745 S2P_Lmt10_Under_Tcell3_01 "电池单体低温三级报警温度";
CM_ SG_ 2417159745 S2P_Lmt10_Under_DTcell3_01 "单体低温3级告警消除回差阈值";
CM_ SG_ 2417159746 S2P_Lmt10_Under_Tcell1_02 "电池单体低温一级报警温度";
CM_ SG_ 2417159746 S2P_Lmt10_Under_DTcell1_02 "单体低温1级告警消除回差阈值";
CM_ SG_ 2417159746 S2P_Lmt10_Under_Tcell2_02 "电池单体低温二级报警温度";
CM_ SG_ 2417159746 S2P_Lmt10_Under_DTcell2_02 "单体低温2级告警消除回差阈值";
CM_ SG_ 2417159746 S2P_Lmt10_Under_Tcell3_02 "电池单体低温三级报警温度";
CM_ SG_ 2417159746 S2P_Lmt10_Under_DTcell3_02 "单体低温3级告警消除回差阈值";
CM_ SG_ 2417159747 S2P_Lmt10_Under_Tcell1_03 "电池单体低温一级报警温度";
CM_ SG_ 2417159747 S2P_Lmt10_Under_DTcell1_03 "单体低温1级告警消除回差阈值";
CM_ SG_ 2417159747 S2P_Lmt10_Under_Tcell2_03 "电池单体低温二级报警温度";
CM_ SG_ 2417159747 S2P_Lmt10_Under_DTcell2_03 "单体低温2级告警消除回差阈值";
CM_ SG_ 2417159747 S2P_Lmt10_Under_Tcell3_03 "电池单体低温三级报警温度";
CM_ SG_ 2417159747 S2P_Lmt10_Under_DTcell3_03 "单体低温3级告警消除回差阈值";
CM_ SG_ 2417159748 S2P_Lmt10_Under_Tcell1_04 "电池单体低温一级报警温度";
CM_ SG_ 2417159748 S2P_Lmt10_Under_DTcell1_04 "单体低温1级告警消除回差阈值";
CM_ SG_ 2417159748 S2P_Lmt10_Under_Tcell2_04 "电池单体低温二级报警温度";
CM_ SG_ 2417159748 S2P_Lmt10_Under_DTcell2_04 "单体低温2级告警消除回差阈值";
CM_ SG_ 2417159748 S2P_Lmt10_Under_Tcell3_04 "电池单体低温三级报警温度";
CM_ SG_ 2417159748 S2P_Lmt10_Under_DTcell3_04 "单体低温3级告警消除回差阈值";
CM_ SG_ 2417159749 S2P_Lmt10_Under_Tcell1_05 "电池单体低温一级报警温度";
CM_ SG_ 2417159749 S2P_Lmt10_Under_DTcell1_05 "单体低温1级告警消除回差阈值";
CM_ SG_ 2417159749 S2P_Lmt10_Under_Tcell2_05 "电池单体低温二级报警温度";
CM_ SG_ 2417159749 S2P_Lmt10_Under_DTcell2_05 "单体低温2级告警消除回差阈值";
CM_ SG_ 2417159749 S2P_Lmt10_Under_Tcell3_05 "电池单体低温三级报警温度";
CM_ SG_ 2417159749 S2P_Lmt10_Under_DTcell3_05 "单体低温3级告警消除回差阈值";
CM_ SG_ 2417159750 S2P_Lmt10_Under_Tcell1_06 "电池单体低温一级报警温度";
CM_ SG_ 2417159750 S2P_Lmt10_Under_DTcell1_06 "单体低温1级告警消除回差阈值";
CM_ SG_ 2417159750 S2P_Lmt10_Under_Tcell2_06 "电池单体低温二级报警温度";
CM_ SG_ 2417159750 S2P_Lmt10_Under_DTcell2_06 "单体低温2级告警消除回差阈值";
CM_ SG_ 2417159750 S2P_Lmt10_Under_Tcell3_06 "电池单体低温三级报警温度";
CM_ SG_ 2417159750 S2P_Lmt10_Under_DTcell3_06 "单体低温3级告警消除回差阈值";
CM_ SG_ 2417159751 S2P_Lmt10_Under_Tcell1_07 "电池单体低温一级报警温度";
CM_ SG_ 2417159751 S2P_Lmt10_Under_DTcell1_07 "单体低温1级告警消除回差阈值";
CM_ SG_ 2417159751 S2P_Lmt10_Under_Tcell2_07 "电池单体低温二级报警温度";
CM_ SG_ 2417159751 S2P_Lmt10_Under_DTcell2_07 "单体低温2级告警消除回差阈值";
CM_ SG_ 2417159751 S2P_Lmt10_Under_Tcell3_07 "电池单体低温三级报警温度";
CM_ SG_ 2417159751 S2P_Lmt10_Under_DTcell3_07 "单体低温3级告警消除回差阈值";
CM_ SG_ 2417159752 S2P_Lmt10_Under_Tcell1_08 "电池单体低温一级报警温度";
CM_ SG_ 2417159752 S2P_Lmt10_Under_DTcell1_08 "单体低温1级告警消除回差阈值";
CM_ SG_ 2417159752 S2P_Lmt10_Under_Tcell2_08 "电池单体低温二级报警温度";
CM_ SG_ 2417159752 S2P_Lmt10_Under_DTcell2_08 "单体低温2级告警消除回差阈值";
CM_ SG_ 2417159752 S2P_Lmt10_Under_Tcell3_08 "电池单体低温三级报警温度";
CM_ SG_ 2417159752 S2P_Lmt10_Under_DTcell3_08 "单体低温3级告警消除回差阈值";
CM_ SG_ 2417159753 S2P_Lmt10_Under_Tcell1_09 "电池单体低温一级报警温度";
CM_ SG_ 2417159753 S2P_Lmt10_Under_DTcell1_09 "单体低温1级告警消除回差阈值";
CM_ SG_ 2417159753 S2P_Lmt10_Under_Tcell2_09 "电池单体低温二级报警温度";
CM_ SG_ 2417159753 S2P_Lmt10_Under_DTcell2_09 "单体低温2级告警消除回差阈值";
CM_ SG_ 2417159753 S2P_Lmt10_Under_Tcell3_09 "电池单体低温三级报警温度";
CM_ SG_ 2417159753 S2P_Lmt10_Under_DTcell3_09 "单体低温3级告警消除回差阈值";
CM_ SG_ 2417159754 S2P_Lmt10_Under_Tcell1_10 "电池单体低温一级报警温度";
CM_ SG_ 2417159754 S2P_Lmt10_Under_DTcell1_10 "单体低温1级告警消除回差阈值";
CM_ SG_ 2417159754 S2P_Lmt10_Under_Tcell2_10 "电池单体低温二级报警温度";
CM_ SG_ 2417159754 S2P_Lmt10_Under_DTcell2_10 "单体低温2级告警消除回差阈值";
CM_ SG_ 2417159754 S2P_Lmt10_Under_Tcell3_10 "电池单体低温三级报警温度";
CM_ SG_ 2417159754 S2P_Lmt10_Under_DTcell3_10 "单体低温3级告警消除回差阈值";
CM_ SG_ 2417159755 S2P_Lmt10_Under_Tcell1_11 "电池单体低温一级报警温度";
CM_ SG_ 2417159755 S2P_Lmt10_Under_DTcell1_11 "单体低温1级告警消除回差阈值";
CM_ SG_ 2417159755 S2P_Lmt10_Under_Tcell2_11 "电池单体低温二级报警温度";
CM_ SG_ 2417159755 S2P_Lmt10_Under_DTcell2_11 "单体低温2级告警消除回差阈值";
CM_ SG_ 2417159755 S2P_Lmt10_Under_Tcell3_11 "电池单体低温三级报警温度";
CM_ SG_ 2417159755 S2P_Lmt10_Under_DTcell3_11 "单体低温3级告警消除回差阈值";
CM_ SG_ 2417159756 S2P_Lmt10_Under_Tcell1_12 "电池单体低温一级报警温度";
CM_ SG_ 2417159756 S2P_Lmt10_Under_DTcell1_12 "单体低温1级告警消除回差阈值";
CM_ SG_ 2417159756 S2P_Lmt10_Under_Tcell2_12 "电池单体低温二级报警温度";
CM_ SG_ 2417159756 S2P_Lmt10_Under_DTcell2_12 "单体低温2级告警消除回差阈值";
CM_ SG_ 2417159756 S2P_Lmt10_Under_Tcell3_12 "电池单体低温三级报警温度";
CM_ SG_ 2417159756 S2P_Lmt10_Under_DTcell3_12 "单体低温3级告警消除回差阈值";
CM_ SG_ 2417159757 S2P_Lmt10_Under_Tcell1_13 "电池单体低温一级报警温度";
CM_ SG_ 2417159757 S2P_Lmt10_Under_DTcell1_13 "单体低温1级告警消除回差阈值";
CM_ SG_ 2417159757 S2P_Lmt10_Under_Tcell2_13 "电池单体低温二级报警温度";
CM_ SG_ 2417159757 S2P_Lmt10_Under_DTcell2_13 "单体低温2级告警消除回差阈值";
CM_ SG_ 2417159757 S2P_Lmt10_Under_Tcell3_13 "电池单体低温三级报警温度";
CM_ SG_ 2417159757 S2P_Lmt10_Under_DTcell3_13 "单体低温3级告警消除回差阈值";
CM_ SG_ 2417159758 S2P_Lmt10_Under_Tcell1_14 "电池单体低温一级报警温度";
CM_ SG_ 2417159758 S2P_Lmt10_Under_DTcell1_14 "单体低温1级告警消除回差阈值";
CM_ SG_ 2417159758 S2P_Lmt10_Under_Tcell2_14 "电池单体低温二级报警温度";
CM_ SG_ 2417159758 S2P_Lmt10_Under_DTcell2_14 "单体低温2级告警消除回差阈值";
CM_ SG_ 2417159758 S2P_Lmt10_Under_Tcell3_14 "电池单体低温三级报警温度";
CM_ SG_ 2417159758 S2P_Lmt10_Under_DTcell3_14 "单体低温3级告警消除回差阈值";
CM_ SG_ 2417159759 S2P_Lmt10_Under_Tcell1_15 "电池单体低温一级报警温度";
CM_ SG_ 2417159759 S2P_Lmt10_Under_DTcell1_15 "单体低温1级告警消除回差阈值";
CM_ SG_ 2417159759 S2P_Lmt10_Under_Tcell2_15 "电池单体低温二级报警温度";
CM_ SG_ 2417159759 S2P_Lmt10_Under_DTcell2_15 "单体低温2级告警消除回差阈值";
CM_ SG_ 2417159759 S2P_Lmt10_Under_Tcell3_15 "电池单体低温三级报警温度";
CM_ SG_ 2417159759 S2P_Lmt10_Under_DTcell3_15 "单体低温3级告警消除回差阈值";
CM_ SG_ 2417159760 S2P_Lmt10_Under_Tcell1_16 "电池单体低温一级报警温度";
CM_ SG_ 2417159760 S2P_Lmt10_Under_DTcell1_16 "单体低温1级告警消除回差阈值";
CM_ SG_ 2417159760 S2P_Lmt10_Under_Tcell2_16 "电池单体低温二级报警温度";
CM_ SG_ 2417159760 S2P_Lmt10_Under_DTcell2_16 "单体低温2级告警消除回差阈值";
CM_ SG_ 2417159760 S2P_Lmt10_Under_Tcell3_16 "电池单体低温三级报警温度";
CM_ SG_ 2417159760 S2P_Lmt10_Under_DTcell3_16 "单体低温3级告警消除回差阈值";
CM_ SG_ 2417159761 S2P_Lmt10_Under_Tcell1_17 "电池单体低温一级报警温度";
CM_ SG_ 2417159761 S2P_Lmt10_Under_DTcell1_17 "单体低温1级告警消除回差阈值";
CM_ SG_ 2417159761 S2P_Lmt10_Under_Tcell2_17 "电池单体低温二级报警温度";
CM_ SG_ 2417159761 S2P_Lmt10_Under_DTcell2_17 "单体低温2级告警消除回差阈值";
CM_ SG_ 2417159761 S2P_Lmt10_Under_Tcell3_17 "电池单体低温三级报警温度";
CM_ SG_ 2417159761 S2P_Lmt10_Under_DTcell3_17 "单体低温3级告警消除回差阈值";
CM_ SG_ 2417159762 S2P_Lmt10_Under_Tcell1_18 "电池单体低温一级报警温度";
CM_ SG_ 2417159762 S2P_Lmt10_Under_DTcell1_18 "单体低温1级告警消除回差阈值";
CM_ SG_ 2417159762 S2P_Lmt10_Under_Tcell2_18 "电池单体低温二级报警温度";
CM_ SG_ 2417159762 S2P_Lmt10_Under_DTcell2_18 "单体低温2级告警消除回差阈值";
CM_ SG_ 2417159762 S2P_Lmt10_Under_Tcell3_18 "电池单体低温三级报警温度";
CM_ SG_ 2417159762 S2P_Lmt10_Under_DTcell3_18 "单体低温3级告警消除回差阈值";
CM_ SG_ 2417159763 S2P_Lmt10_Under_Tcell1_19 "电池单体低温一级报警温度";
CM_ SG_ 2417159763 S2P_Lmt10_Under_DTcell1_19 "单体低温1级告警消除回差阈值";
CM_ SG_ 2417159763 S2P_Lmt10_Under_Tcell2_19 "电池单体低温二级报警温度";
CM_ SG_ 2417159763 S2P_Lmt10_Under_DTcell2_19 "单体低温2级告警消除回差阈值";
CM_ SG_ 2417159763 S2P_Lmt10_Under_Tcell3_19 "电池单体低温三级报警温度";
CM_ SG_ 2417159763 S2P_Lmt10_Under_DTcell3_19 "单体低温3级告警消除回差阈值";
CM_ SG_ 2417159764 S2P_Lmt10_Under_Tcell1_20 "电池单体低温一级报警温度";
CM_ SG_ 2417159764 S2P_Lmt10_Under_DTcell1_20 "单体低温1级告警消除回差阈值";
CM_ SG_ 2417159764 S2P_Lmt10_Under_Tcell2_20 "电池单体低温二级报警温度";
CM_ SG_ 2417159764 S2P_Lmt10_Under_DTcell2_20 "单体低温2级告警消除回差阈值";
CM_ SG_ 2417159764 S2P_Lmt10_Under_Tcell3_20 "电池单体低温三级报警温度";
CM_ SG_ 2417159764 S2P_Lmt10_Under_DTcell3_20 "单体低温3级告警消除回差阈值";
CM_ SG_ 2417159765 S2P_Lmt10_Under_Tcell1_21 "电池单体低温一级报警温度";
CM_ SG_ 2417159765 S2P_Lmt10_Under_DTcell1_21 "单体低温1级告警消除回差阈值";
CM_ SG_ 2417159765 S2P_Lmt10_Under_Tcell2_21 "电池单体低温二级报警温度";
CM_ SG_ 2417159765 S2P_Lmt10_Under_DTcell2_21 "单体低温2级告警消除回差阈值";
CM_ SG_ 2417159765 S2P_Lmt10_Under_Tcell3_21 "电池单体低温三级报警温度";
CM_ SG_ 2417159765 S2P_Lmt10_Under_DTcell3_21 "单体低温3级告警消除回差阈值";
CM_ SG_ 2417159766 S2P_Lmt10_Under_Tcell1_22 "电池单体低温一级报警温度";
CM_ SG_ 2417159766 S2P_Lmt10_Under_DTcell1_22 "单体低温1级告警消除回差阈值";
CM_ SG_ 2417159766 S2P_Lmt10_Under_Tcell2_22 "电池单体低温二级报警温度";
CM_ SG_ 2417159766 S2P_Lmt10_Under_DTcell2_22 "单体低温2级告警消除回差阈值";
CM_ SG_ 2417159766 S2P_Lmt10_Under_Tcell3_22 "电池单体低温三级报警温度";
CM_ SG_ 2417159766 S2P_Lmt10_Under_DTcell3_22 "单体低温3级告警消除回差阈值";
CM_ SG_ 2417159767 S2P_Lmt10_Under_Tcell1_23 "电池单体低温一级报警温度";
CM_ SG_ 2417159767 S2P_Lmt10_Under_DTcell1_23 "单体低温1级告警消除回差阈值";
CM_ SG_ 2417159767 S2P_Lmt10_Under_Tcell2_23 "电池单体低温二级报警温度";
CM_ SG_ 2417159767 S2P_Lmt10_Under_DTcell2_23 "单体低温2级告警消除回差阈值";
CM_ SG_ 2417159767 S2P_Lmt10_Under_Tcell3_23 "电池单体低温三级报警温度";
CM_ SG_ 2417159767 S2P_Lmt10_Under_DTcell3_23 "单体低温3级告警消除回差阈值";
CM_ SG_ 2417159768 S2P_Lmt10_Under_Tcell1_24 "电池单体低温一级报警温度";
CM_ SG_ 2417159768 S2P_Lmt10_Under_DTcell1_24 "单体低温1级告警消除回差阈值";
CM_ SG_ 2417159768 S2P_Lmt10_Under_Tcell2_24 "电池单体低温二级报警温度";
CM_ SG_ 2417159768 S2P_Lmt10_Under_DTcell2_24 "单体低温2级告警消除回差阈值";
CM_ SG_ 2417159768 S2P_Lmt10_Under_Tcell3_24 "电池单体低温三级报警温度";
CM_ SG_ 2417159768 S2P_Lmt10_Under_DTcell3_24 "单体低温3级告警消除回差阈值";
CM_ SG_ 2417159769 S2P_Lmt10_Under_Tcell1_25 "电池单体低温一级报警温度";
CM_ SG_ 2417159769 S2P_Lmt10_Under_DTcell1_25 "单体低温1级告警消除回差阈值";
CM_ SG_ 2417159769 S2P_Lmt10_Under_Tcell2_25 "电池单体低温二级报警温度";
CM_ SG_ 2417159769 S2P_Lmt10_Under_DTcell2_25 "单体低温2级告警消除回差阈值";
CM_ SG_ 2417159769 S2P_Lmt10_Under_Tcell3_25 "电池单体低温三级报警温度";
CM_ SG_ 2417159769 S2P_Lmt10_Under_DTcell3_25 "单体低温3级告警消除回差阈值";
CM_ SG_ 2417159770 S2P_Lmt10_Under_Tcell1_26 "电池单体低温一级报警温度";
CM_ SG_ 2417159770 S2P_Lmt10_Under_DTcell1_26 "单体低温1级告警消除回差阈值";
CM_ SG_ 2417159770 S2P_Lmt10_Under_Tcell2_26 "电池单体低温二级报警温度";
CM_ SG_ 2417159770 S2P_Lmt10_Under_DTcell2_26 "单体低温2级告警消除回差阈值";
CM_ SG_ 2417159770 S2P_Lmt10_Under_Tcell3_26 "电池单体低温三级报警温度";
CM_ SG_ 2417159770 S2P_Lmt10_Under_DTcell3_26 "单体低温3级告警消除回差阈值";
CM_ SG_ 2417159771 S2P_Lmt10_Under_Tcell1_27 "电池单体低温一级报警温度";
CM_ SG_ 2417159771 S2P_Lmt10_Under_DTcell1_27 "单体低温1级告警消除回差阈值";
CM_ SG_ 2417159771 S2P_Lmt10_Under_Tcell2_27 "电池单体低温二级报警温度";
CM_ SG_ 2417159771 S2P_Lmt10_Under_DTcell2_27 "单体低温2级告警消除回差阈值";
CM_ SG_ 2417159771 S2P_Lmt10_Under_Tcell3_27 "电池单体低温三级报警温度";
CM_ SG_ 2417159771 S2P_Lmt10_Under_DTcell3_27 "单体低温3级告警消除回差阈值";
CM_ SG_ 2417159772 S2P_Lmt10_Under_Tcell1_28 "电池单体低温一级报警温度";
CM_ SG_ 2417159772 S2P_Lmt10_Under_DTcell1_28 "单体低温1级告警消除回差阈值";
CM_ SG_ 2417159772 S2P_Lmt10_Under_Tcell2_28 "电池单体低温二级报警温度";
CM_ SG_ 2417159772 S2P_Lmt10_Under_DTcell2_28 "单体低温2级告警消除回差阈值";
CM_ SG_ 2417159772 S2P_Lmt10_Under_Tcell3_28 "电池单体低温三级报警温度";
CM_ SG_ 2417159772 S2P_Lmt10_Under_DTcell3_28 "单体低温3级告警消除回差阈值";
CM_ SG_ 2417159773 S2P_Lmt10_Under_Tcell1_29 "电池单体低温一级报警温度";
CM_ SG_ 2417159773 S2P_Lmt10_Under_DTcell1_29 "单体低温1级告警消除回差阈值";
CM_ SG_ 2417159773 S2P_Lmt10_Under_Tcell2_29 "电池单体低温二级报警温度";
CM_ SG_ 2417159773 S2P_Lmt10_Under_DTcell2_29 "单体低温2级告警消除回差阈值";
CM_ SG_ 2417159773 S2P_Lmt10_Under_Tcell3_29 "电池单体低温三级报警温度";
CM_ SG_ 2417159773 S2P_Lmt10_Under_DTcell3_29 "单体低温3级告警消除回差阈值";
CM_ SG_ 2417159774 S2P_Lmt10_Under_Tcell1_30 "电池单体低温一级报警温度";
CM_ SG_ 2417159774 S2P_Lmt10_Under_DTcell1_30 "单体低温1级告警消除回差阈值";
CM_ SG_ 2417159774 S2P_Lmt10_Under_Tcell2_30 "电池单体低温二级报警温度";
CM_ SG_ 2417159774 S2P_Lmt10_Under_DTcell2_30 "单体低温2级告警消除回差阈值";
CM_ SG_ 2417159774 S2P_Lmt10_Under_Tcell3_30 "电池单体低温三级报警温度";
CM_ SG_ 2417159774 S2P_Lmt10_Under_DTcell3_30 "单体低温3级告警消除回差阈值";
CM_ SG_ 2417159775 S2P_Lmt10_Under_Tcell1_31 "电池单体低温一级报警温度";
CM_ SG_ 2417159775 S2P_Lmt10_Under_DTcell1_31 "单体低温1级告警消除回差阈值";
CM_ SG_ 2417159775 S2P_Lmt10_Under_Tcell2_31 "电池单体低温二级报警温度";
CM_ SG_ 2417159775 S2P_Lmt10_Under_DTcell2_31 "单体低温2级告警消除回差阈值";
CM_ SG_ 2417159775 S2P_Lmt10_Under_Tcell3_31 "电池单体低温三级报警温度";
CM_ SG_ 2417159775 S2P_Lmt10_Under_DTcell3_31 "单体低温3级告警消除回差阈值";
CM_ SG_ 2417159776 S2P_Lmt10_Under_Tcell1_32 "电池单体低温一级报警温度";
CM_ SG_ 2417159776 S2P_Lmt10_Under_DTcell1_32 "单体低温1级告警消除回差阈值";
CM_ SG_ 2417159776 S2P_Lmt10_Under_Tcell2_32 "电池单体低温二级报警温度";
CM_ SG_ 2417159776 S2P_Lmt10_Under_DTcell2_32 "单体低温2级告警消除回差阈值";
CM_ SG_ 2417159776 S2P_Lmt10_Under_Tcell3_32 "电池单体低温三级报警温度";
CM_ SG_ 2417159776 S2P_Lmt10_Under_DTcell3_32 "单体低温3级告警消除回差阈值";
CM_ SG_ 2417159777 S2P_Lmt10_Under_Tcell1_33 "电池单体低温一级报警温度";
CM_ SG_ 2417159777 S2P_Lmt10_Under_DTcell1_33 "单体低温1级告警消除回差阈值";
CM_ SG_ 2417159777 S2P_Lmt10_Under_Tcell2_33 "电池单体低温二级报警温度";
CM_ SG_ 2417159777 S2P_Lmt10_Under_DTcell2_33 "单体低温2级告警消除回差阈值";
CM_ SG_ 2417159777 S2P_Lmt10_Under_Tcell3_33 "电池单体低温三级报警温度";
CM_ SG_ 2417159777 S2P_Lmt10_Under_DTcell3_33 "单体低温3级告警消除回差阈值";
CM_ SG_ 2417159778 S2P_Lmt10_Under_Tcell1_34 "电池单体低温一级报警温度";
CM_ SG_ 2417159778 S2P_Lmt10_Under_DTcell1_34 "单体低温1级告警消除回差阈值";
CM_ SG_ 2417159778 S2P_Lmt10_Under_Tcell2_34 "电池单体低温二级报警温度";
CM_ SG_ 2417159778 S2P_Lmt10_Under_DTcell2_34 "单体低温2级告警消除回差阈值";
CM_ SG_ 2417159778 S2P_Lmt10_Under_Tcell3_34 "电池单体低温三级报警温度";
CM_ SG_ 2417159778 S2P_Lmt10_Under_DTcell3_34 "单体低温3级告警消除回差阈值";
CM_ SG_ 2417159779 S2P_Lmt10_Under_Tcell1_35 "电池单体低温一级报警温度";
CM_ SG_ 2417159779 S2P_Lmt10_Under_DTcell1_35 "单体低温1级告警消除回差阈值";
CM_ SG_ 2417159779 S2P_Lmt10_Under_Tcell2_35 "电池单体低温二级报警温度";
CM_ SG_ 2417159779 S2P_Lmt10_Under_DTcell2_35 "单体低温2级告警消除回差阈值";
CM_ SG_ 2417159779 S2P_Lmt10_Under_Tcell3_35 "电池单体低温三级报警温度";
CM_ SG_ 2417159779 S2P_Lmt10_Under_DTcell3_35 "单体低温3级告警消除回差阈值";
CM_ SG_ 2417159780 S2P_Lmt10_Under_Tcell1_36 "电池单体低温一级报警温度";
CM_ SG_ 2417159780 S2P_Lmt10_Under_DTcell1_36 "单体低温1级告警消除回差阈值";
CM_ SG_ 2417159780 S2P_Lmt10_Under_Tcell2_36 "电池单体低温二级报警温度";
CM_ SG_ 2417159780 S2P_Lmt10_Under_DTcell2_36 "单体低温2级告警消除回差阈值";
CM_ SG_ 2417159780 S2P_Lmt10_Under_Tcell3_36 "电池单体低温三级报警温度";
CM_ SG_ 2417159780 S2P_Lmt10_Under_DTcell3_36 "单体低温3级告警消除回差阈值";
CM_ SG_ 2417159781 S2P_Lmt10_Under_Tcell1_37 "电池单体低温一级报警温度";
CM_ SG_ 2417159781 S2P_Lmt10_Under_DTcell1_37 "单体低温1级告警消除回差阈值";
CM_ SG_ 2417159781 S2P_Lmt10_Under_Tcell2_37 "电池单体低温二级报警温度";
CM_ SG_ 2417159781 S2P_Lmt10_Under_DTcell2_37 "单体低温2级告警消除回差阈值";
CM_ SG_ 2417159781 S2P_Lmt10_Under_Tcell3_37 "电池单体低温三级报警温度";
CM_ SG_ 2417159781 S2P_Lmt10_Under_DTcell3_37 "单体低温3级告警消除回差阈值";
CM_ SG_ 2417159782 S2P_Lmt10_Under_Tcell1_38 "电池单体低温一级报警温度";
CM_ SG_ 2417159782 S2P_Lmt10_Under_DTcell1_38 "单体低温1级告警消除回差阈值";
CM_ SG_ 2417159782 S2P_Lmt10_Under_Tcell2_38 "电池单体低温二级报警温度";
CM_ SG_ 2417159782 S2P_Lmt10_Under_DTcell2_38 "单体低温2级告警消除回差阈值";
CM_ SG_ 2417159782 S2P_Lmt10_Under_Tcell3_38 "电池单体低温三级报警温度";
CM_ SG_ 2417159782 S2P_Lmt10_Under_DTcell3_38 "单体低温3级告警消除回差阈值";
CM_ SG_ 2417159783 S2P_Lmt10_Under_Tcell1_39 "电池单体低温一级报警温度";
CM_ SG_ 2417159783 S2P_Lmt10_Under_DTcell1_39 "单体低温1级告警消除回差阈值";
CM_ SG_ 2417159783 S2P_Lmt10_Under_Tcell2_39 "电池单体低温二级报警温度";
CM_ SG_ 2417159783 S2P_Lmt10_Under_DTcell2_39 "单体低温2级告警消除回差阈值";
CM_ SG_ 2417159783 S2P_Lmt10_Under_Tcell3_39 "电池单体低温三级报警温度";
CM_ SG_ 2417159783 S2P_Lmt10_Under_DTcell3_39 "单体低温3级告警消除回差阈值";
VERSION ""

NS_ :

BS_:

BU_: MBMU PC SBMU IMM ETH DCDC LEMS

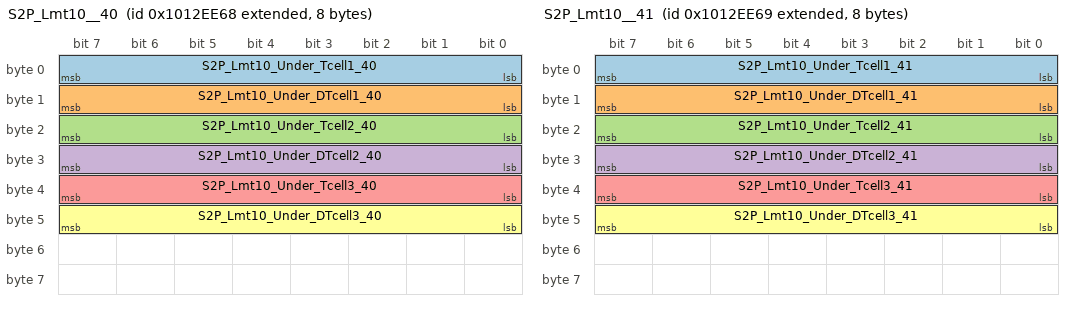
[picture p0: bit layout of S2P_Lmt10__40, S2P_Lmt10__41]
BO_ 2417159784 S2P_Lmt10__40: 8 SBMU
 SG_ S2P_Lmt10_Under_Tcell1_40 : 0|8@1+ (1,-50) [-50|205] "℃"  PC
 SG_ S2P_Lmt10_Under_DTcell1_40 : 8|8@1+ (1,-50) [-50|205] "℃"  PC
 SG_ S2P_Lmt10_Under_Tcell2_40 : 16|8@1+ (1,-50) [-50|205] "℃"  PC
 SG_ S2P_Lmt10_Under_DTcell2_40 : 24|8@1+ (1,-50) [-50|205] "℃"  PC
 SG_ S2P_Lmt10_Under_Tcell3_40 : 32|8@1+ (1,-50) [-50|205] "℃"  PC
 SG_ S2P_Lmt10_Under_DTcell3_40 : 40|8@1+ (1,-50) [-50|205] "℃"  PC

BO_ 2417159785 S2P_Lmt10__41: 8 SBMU
 SG_ S2P_Lmt10_Under_Tcell1_41 : 0|8@1+ (1,-50) [-50|205] "℃"  PC
 SG_ S2P_Lmt10_Under_DTcell1_41 : 8|8@1+ (1,-50) [-50|205] "℃"  PC
 SG_ S2P_Lmt10_Under_Tcell2_41 : 16|8@1+ (1,-50) [-50|205] "℃"  PC
 SG_ S2P_Lmt10_Under_DTcell2_41 : 24|8@1+ (1,-50) [-50|205] "℃"  PC
 SG_ S2P_Lmt10_Under_Tcell3_41 : 32|8@1+ (1,-50) [-50|205] "℃"  PC
 SG_ S2P_Lmt10_Under_DTcell3_41 : 40|8@1+ (1,-50) [-50|205] "℃"  PC

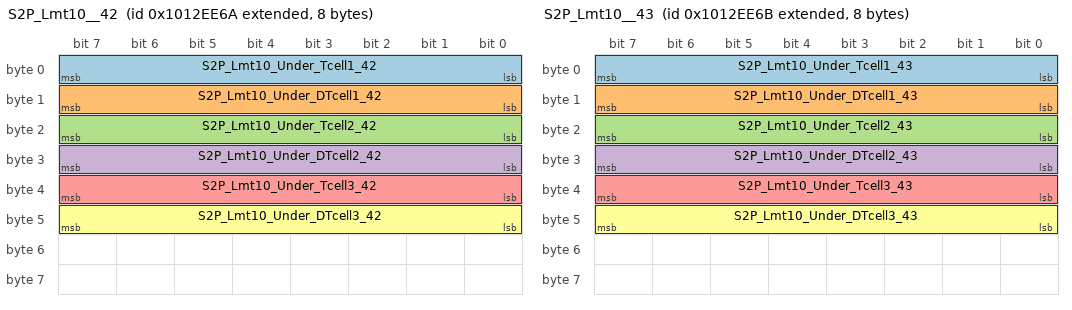
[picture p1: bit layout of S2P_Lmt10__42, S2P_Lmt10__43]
BO_ 2417159786 S2P_Lmt10__42: 8 SBMU
 SG_ S2P_Lmt10_Under_Tcell1_42 : 0|8@1+ (1,-50) [-50|205] "℃"  PC
 SG_ S2P_Lmt10_Under_DTcell1_42 : 8|8@1+ (1,-50) [-50|205] "℃"  PC
 SG_ S2P_Lmt10_Under_Tcell2_42 : 16|8@1+ (1,-50) [-50|205] "℃"  PC
 SG_ S2P_Lmt10_Under_DTcell2_42 : 24|8@1+ (1,-50) [-50|205] "℃"  PC
 SG_ S2P_Lmt10_Under_Tcell3_42 : 32|8@1+ (1,-50) [-50|205] "℃"  PC
 SG_ S2P_Lmt10_Under_DTcell3_42 : 40|8@1+ (1,-50) [-50|205] "℃"  PC

BO_ 2417159787 S2P_Lmt10__43: 8 SBMU
 SG_ S2P_Lmt10_Under_Tcell1_43 : 0|8@1+ (1,-50) [-50|205] "℃"  PC
 SG_ S2P_Lmt10_Under_DTcell1_43 : 8|8@1+ (1,-50) [-50|205] "℃"  PC
 SG_ S2P_Lmt10_Under_Tcell2_43 : 16|8@1+ (1,-50) [-50|205] "℃"  PC
 SG_ S2P_Lmt10_Under_DTcell2_43 : 24|8@1+ (1,-50) [-50|205] "℃"  PC
 SG_ S2P_Lmt10_Under_Tcell3_43 : 32|8@1+ (1,-50) [-50|205] "℃"  PC
 SG_ S2P_Lmt10_Under_DTcell3_43 : 40|8@1+ (1,-50) [-50|205] "℃"  PC

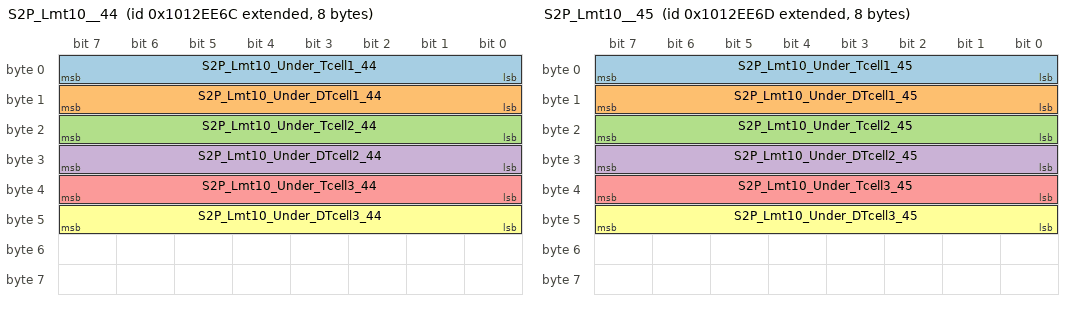
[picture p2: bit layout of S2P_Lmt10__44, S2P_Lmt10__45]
BO_ 2417159788 S2P_Lmt10__44: 8 SBMU
 SG_ S2P_Lmt10_Under_Tcell1_44 : 0|8@1+ (1,-50) [-50|205] "℃"  PC
 SG_ S2P_Lmt10_Under_DTcell1_44 : 8|8@1+ (1,-50) [-50|205] "℃"  PC
 SG_ S2P_Lmt10_Under_Tcell2_44 : 16|8@1+ (1,-50) [-50|205] "℃"  PC
 SG_ S2P_Lmt10_Under_DTcell2_44 : 24|8@1+ (1,-50) [-50|205] "℃"  PC
 SG_ S2P_Lmt10_Under_Tcell3_44 : 32|8@1+ (1,-50) [-50|205] "℃"  PC
 SG_ S2P_Lmt10_Under_DTcell3_44 : 40|8@1+ (1,-50) [-50|205] "℃"  PC

BO_ 2417159789 S2P_Lmt10__45: 8 SBMU
 SG_ S2P_Lmt10_Under_Tcell1_45 : 0|8@1+ (1,-50) [-50|205] "℃"  PC
 SG_ S2P_Lmt10_Under_DTcell1_45 : 8|8@1+ (1,-50) [-50|205] "℃"  PC
 SG_ S2P_Lmt10_Under_Tcell2_45 : 16|8@1+ (1,-50) [-50|205] "℃"  PC
 SG_ S2P_Lmt10_Under_DTcell2_45 : 24|8@1+ (1,-50) [-50|205] "℃"  PC
 SG_ S2P_Lmt10_Under_Tcell3_45 : 32|8@1+ (1,-50) [-50|205] "℃"  PC
 SG_ S2P_Lmt10_Under_DTcell3_45 : 40|8@1+ (1,-50) [-50|205] "℃"  PC

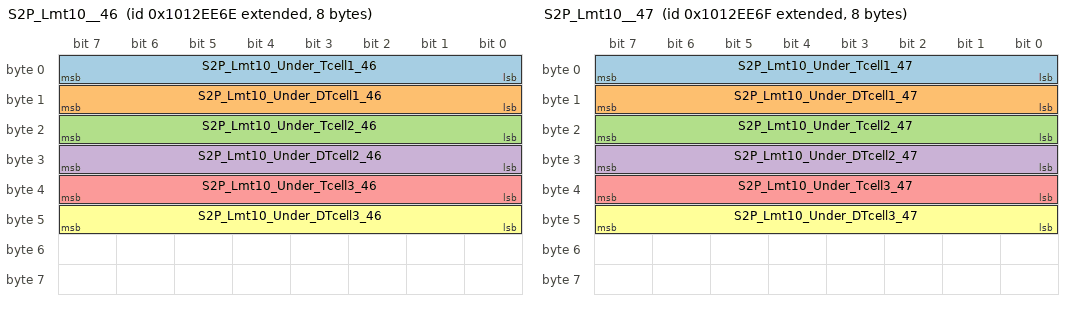
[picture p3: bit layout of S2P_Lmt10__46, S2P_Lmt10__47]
BO_ 2417159790 S2P_Lmt10__46: 8 SBMU
 SG_ S2P_Lmt10_Under_Tcell1_46 : 0|8@1+ (1,-50) [-50|205] "℃"  PC
 SG_ S2P_Lmt10_Under_DTcell1_46 : 8|8@1+ (1,-50) [-50|205] "℃"  PC
 SG_ S2P_Lmt10_Under_Tcell2_46 : 16|8@1+ (1,-50) [-50|205] "℃"  PC
 SG_ S2P_Lmt10_Under_DTcell2_46 : 24|8@1+ (1,-50) [-50|205] "℃"  PC
 SG_ S2P_Lmt10_Under_Tcell3_46 : 32|8@1+ (1,-50) [-50|205] "℃"  PC
 SG_ S2P_Lmt10_Under_DTcell3_46 : 40|8@1+ (1,-50) [-50|205] "℃"  PC

BO_ 2417159791 S2P_Lmt10__47: 8 SBMU
 SG_ S2P_Lmt10_Under_Tcell1_47 : 0|8@1+ (1,-50) [-50|205] "℃"  PC
 SG_ S2P_Lmt10_Under_DTcell1_47 : 8|8@1+ (1,-50) [-50|205] "℃"  PC
 SG_ S2P_Lmt10_Under_Tcell2_47 : 16|8@1+ (1,-50) [-50|205] "℃"  PC
 SG_ S2P_Lmt10_Under_DTcell2_47 : 24|8@1+ (1,-50) [-50|205] "℃"  PC
 SG_ S2P_Lmt10_Under_Tcell3_47 : 32|8@1+ (1,-50) [-50|205] "℃"  PC
 SG_ S2P_Lmt10_Under_DTcell3_47 : 40|8@1+ (1,-50) [-50|205] "℃"  PC

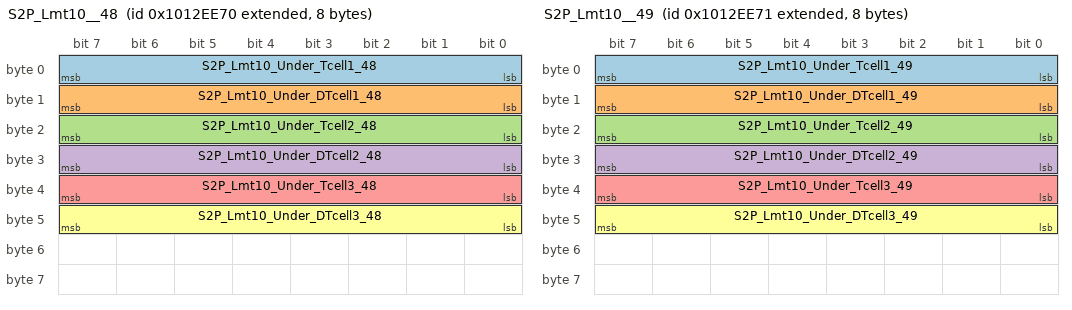
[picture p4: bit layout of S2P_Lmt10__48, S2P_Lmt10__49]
BO_ 2417159792 S2P_Lmt10__48: 8 SBMU
 SG_ S2P_Lmt10_Under_Tcell1_48 : 0|8@1+ (1,-50) [-50|205] "℃"  PC
 SG_ S2P_Lmt10_Under_DTcell1_48 : 8|8@1+ (1,-50) [-50|205] "℃"  PC
 SG_ S2P_Lmt10_Under_Tcell2_48 : 16|8@1+ (1,-50) [-50|205] "℃"  PC
 SG_ S2P_Lmt10_Under_DTcell2_48 : 24|8@1+ (1,-50) [-50|205] "℃"  PC
 SG_ S2P_Lmt10_Under_Tcell3_48 : 32|8@1+ (1,-50) [-50|205] "℃"  PC
 SG_ S2P_Lmt10_Under_DTcell3_48 : 40|8@1+ (1,-50) [-50|205] "℃"  PC

BO_ 2417159793 S2P_Lmt10__49: 8 SBMU
 SG_ S2P_Lmt10_Under_Tcell1_49 : 0|8@1+ (1,-50) [-50|205] "℃"  PC
 SG_ S2P_Lmt10_Under_DTcell1_49 : 8|8@1+ (1,-50) [-50|205] "℃"  PC
 SG_ S2P_Lmt10_Under_Tcell2_49 : 16|8@1+ (1,-50) [-50|205] "℃"  PC
 SG_ S2P_Lmt10_Under_DTcell2_49 : 24|8@1+ (1,-50) [-50|205] "℃"  PC
 SG_ S2P_Lmt10_Under_Tcell3_49 : 32|8@1+ (1,-50) [-50|205] "℃"  PC
 SG_ S2P_Lmt10_Under_DTcell3_49 : 40|8@1+ (1,-50) [-50|205] "℃"  PC

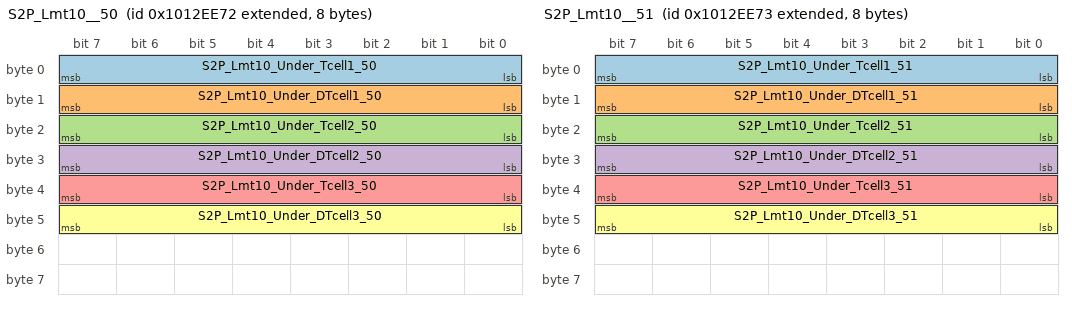
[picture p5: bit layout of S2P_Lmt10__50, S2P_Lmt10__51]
BO_ 2417159794 S2P_Lmt10__50: 8 SBMU
 SG_ S2P_Lmt10_Under_Tcell1_50 : 0|8@1+ (1,-50) [-50|205] "℃"  PC
 SG_ S2P_Lmt10_Under_DTcell1_50 : 8|8@1+ (1,-50) [-50|205] "℃"  PC
 SG_ S2P_Lmt10_Under_Tcell2_50 : 16|8@1+ (1,-50) [-50|205] "℃"  PC
 SG_ S2P_Lmt10_Under_DTcell2_50 : 24|8@1+ (1,-50) [-50|205] "℃"  PC
 SG_ S2P_Lmt10_Under_Tcell3_50 : 32|8@1+ (1,-50) [-50|205] "℃"  PC
 SG_ S2P_Lmt10_Under_DTcell3_50 : 40|8@1+ (1,-50) [-50|205] "℃"  PC

BO_ 2417159795 S2P_Lmt10__51: 8 SBMU
 SG_ S2P_Lmt10_Under_Tcell1_51 : 0|8@1+ (1,-50) [-50|205] "℃"  PC
 SG_ S2P_Lmt10_Under_DTcell1_51 : 8|8@1+ (1,-50) [-50|205] "℃"  PC
 SG_ S2P_Lmt10_Under_Tcell2_51 : 16|8@1+ (1,-50) [-50|205] "℃"  PC
 SG_ S2P_Lmt10_Under_DTcell2_51 : 24|8@1+ (1,-50) [-50|205] "℃"  PC
 SG_ S2P_Lmt10_Under_Tcell3_51 : 32|8@1+ (1,-50) [-50|205] "℃"  PC
 SG_ S2P_Lmt10_Under_DTcell3_51 : 40|8@1+ (1,-50) [-50|205] "℃"  PC

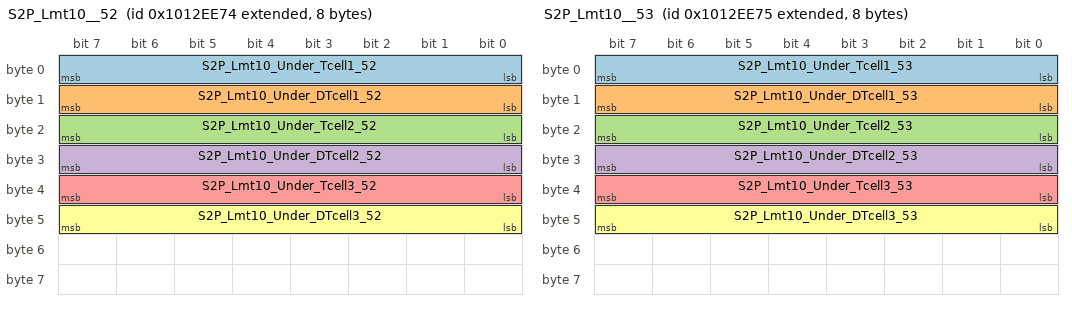
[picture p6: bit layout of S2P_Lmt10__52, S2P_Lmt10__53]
BO_ 2417159796 S2P_Lmt10__52: 8 SBMU
 SG_ S2P_Lmt10_Under_Tcell1_52 : 0|8@1+ (1,-50) [-50|205] "℃"  PC
 SG_ S2P_Lmt10_Under_DTcell1_52 : 8|8@1+ (1,-50) [-50|205] "℃"  PC
 SG_ S2P_Lmt10_Under_Tcell2_52 : 16|8@1+ (1,-50) [-50|205] "℃"  PC
 SG_ S2P_Lmt10_Under_DTcell2_52 : 24|8@1+ (1,-50) [-50|205] "℃"  PC
 SG_ S2P_Lmt10_Under_Tcell3_52 : 32|8@1+ (1,-50) [-50|205] "℃"  PC
 SG_ S2P_Lmt10_Under_DTcell3_52 : 40|8@1+ (1,-50) [-50|205] "℃"  PC

BO_ 2417159797 S2P_Lmt10__53: 8 SBMU
 SG_ S2P_Lmt10_Under_Tcell1_53 : 0|8@1+ (1,-50) [-50|205] "℃"  PC
 SG_ S2P_Lmt10_Under_DTcell1_53 : 8|8@1+ (1,-50) [-50|205] "℃"  PC
 SG_ S2P_Lmt10_Under_Tcell2_53 : 16|8@1+ (1,-50) [-50|205] "℃"  PC
 SG_ S2P_Lmt10_Under_DTcell2_53 : 24|8@1+ (1,-50) [-50|205] "℃"  PC
 SG_ S2P_Lmt10_Under_Tcell3_53 : 32|8@1+ (1,-50) [-50|205] "℃"  PC
 SG_ S2P_Lmt10_Under_DTcell3_53 : 40|8@1+ (1,-50) [-50|205] "℃"  PC

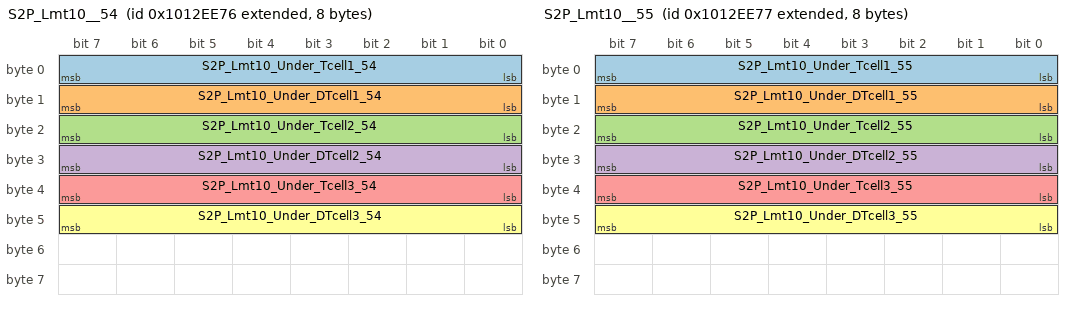
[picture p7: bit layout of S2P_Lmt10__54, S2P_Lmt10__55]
BO_ 2417159798 S2P_Lmt10__54: 8 SBMU
 SG_ S2P_Lmt10_Under_Tcell1_54 : 0|8@1+ (1,-50) [-50|205] "℃"  PC
 SG_ S2P_Lmt10_Under_DTcell1_54 : 8|8@1+ (1,-50) [-50|205] "℃"  PC
 SG_ S2P_Lmt10_Under_Tcell2_54 : 16|8@1+ (1,-50) [-50|205] "℃"  PC
 SG_ S2P_Lmt10_Under_DTcell2_54 : 24|8@1+ (1,-50) [-50|205] "℃"  PC
 SG_ S2P_Lmt10_Under_Tcell3_54 : 32|8@1+ (1,-50) [-50|205] "℃"  PC
 SG_ S2P_Lmt10_Under_DTcell3_54 : 40|8@1+ (1,-50) [-50|205] "℃"  PC

BO_ 2417159799 S2P_Lmt10__55: 8 SBMU
 SG_ S2P_Lmt10_Under_Tcell1_55 : 0|8@1+ (1,-50) [-50|205] "℃"  PC
 SG_ S2P_Lmt10_Under_DTcell1_55 : 8|8@1+ (1,-50) [-50|205] "℃"  PC
 SG_ S2P_Lmt10_Under_Tcell2_55 : 16|8@1+ (1,-50) [-50|205] "℃"  PC
 SG_ S2P_Lmt10_Under_DTcell2_55 : 24|8@1+ (1,-50) [-50|205] "℃"  PC
 SG_ S2P_Lmt10_Under_Tcell3_55 : 32|8@1+ (1,-50) [-50|205] "℃"  PC
 SG_ S2P_Lmt10_Under_DTcell3_55 : 40|8@1+ (1,-50) [-50|205] "℃"  PC

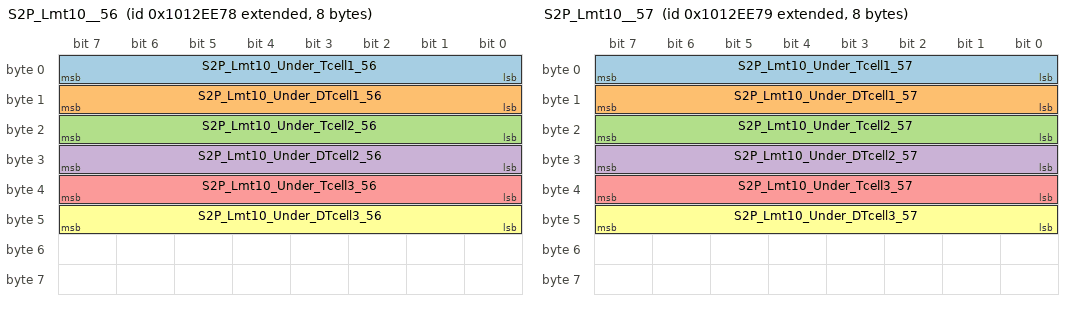
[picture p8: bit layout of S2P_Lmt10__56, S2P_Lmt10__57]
BO_ 2417159800 S2P_Lmt10__56: 8 SBMU
 SG_ S2P_Lmt10_Under_Tcell1_56 : 0|8@1+ (1,-50) [-50|205] "℃"  PC
 SG_ S2P_Lmt10_Under_DTcell1_56 : 8|8@1+ (1,-50) [-50|205] "℃"  PC
 SG_ S2P_Lmt10_Under_Tcell2_56 : 16|8@1+ (1,-50) [-50|205] "℃"  PC
 SG_ S2P_Lmt10_Under_DTcell2_56 : 24|8@1+ (1,-50) [-50|205] "℃"  PC
 SG_ S2P_Lmt10_Under_Tcell3_56 : 32|8@1+ (1,-50) [-50|205] "℃"  PC
 SG_ S2P_Lmt10_Under_DTcell3_56 : 40|8@1+ (1,-50) [-50|205] "℃"  PC

BO_ 2417159801 S2P_Lmt10__57: 8 SBMU
 SG_ S2P_Lmt10_Under_Tcell1_57 : 0|8@1+ (1,-50) [-50|205] "℃"  PC
 SG_ S2P_Lmt10_Under_DTcell1_57 : 8|8@1+ (1,-50) [-50|205] "℃"  PC
 SG_ S2P_Lmt10_Under_Tcell2_57 : 16|8@1+ (1,-50) [-50|205] "℃"  PC
 SG_ S2P_Lmt10_Under_DTcell2_57 : 24|8@1+ (1,-50) [-50|205] "℃"  PC
 SG_ S2P_Lmt10_Under_Tcell3_57 : 32|8@1+ (1,-50) [-50|205] "℃"  PC
 SG_ S2P_Lmt10_Under_DTcell3_57 : 40|8@1+ (1,-50) [-50|205] "℃"  PC

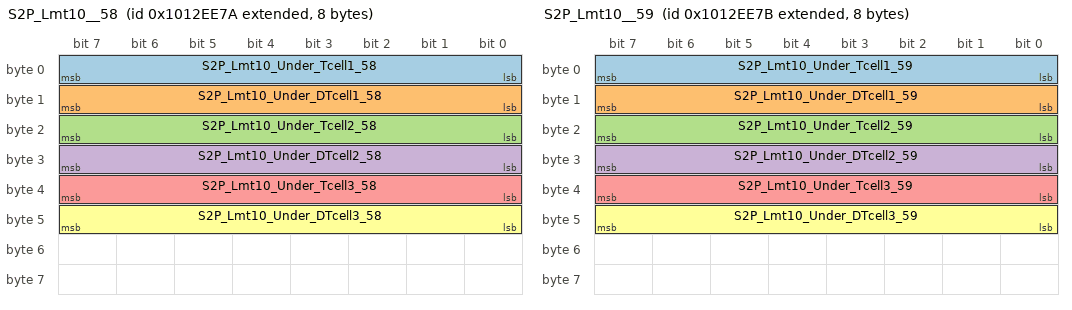
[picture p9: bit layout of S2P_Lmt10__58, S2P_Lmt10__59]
BO_ 2417159802 S2P_Lmt10__58: 8 SBMU
 SG_ S2P_Lmt10_Under_Tcell1_58 : 0|8@1+ (1,-50) [-50|205] "℃"  PC
 SG_ S2P_Lmt10_Under_DTcell1_58 : 8|8@1+ (1,-50) [-50|205] "℃"  PC
 SG_ S2P_Lmt10_Under_Tcell2_58 : 16|8@1+ (1,-50) [-50|205] "℃"  PC
 SG_ S2P_Lmt10_Under_DTcell2_58 : 24|8@1+ (1,-50) [-50|205] "℃"  PC
 SG_ S2P_Lmt10_Under_Tcell3_58 : 32|8@1+ (1,-50) [-50|205] "℃"  PC
 SG_ S2P_Lmt10_Under_DTcell3_58 : 40|8@1+ (1,-50) [-50|205] "℃"  PC

BO_ 2417159803 S2P_Lmt10__59: 8 SBMU
 SG_ S2P_Lmt10_Under_Tcell1_59 : 0|8@1+ (1,-50) [-50|205] "℃"  PC
 SG_ S2P_Lmt10_Under_DTcell1_59 : 8|8@1+ (1,-50) [-50|205] "℃"  PC
 SG_ S2P_Lmt10_Under_Tcell2_59 : 16|8@1+ (1,-50) [-50|205] "℃"  PC
 SG_ S2P_Lmt10_Under_DTcell2_59 : 24|8@1+ (1,-50) [-50|205] "℃"  PC
 SG_ S2P_Lmt10_Under_Tcell3_59 : 32|8@1+ (1,-50) [-50|205] "℃"  PC
 SG_ S2P_Lmt10_Under_DTcell3_59 : 40|8@1+ (1,-50) [-50|205] "℃"  PC

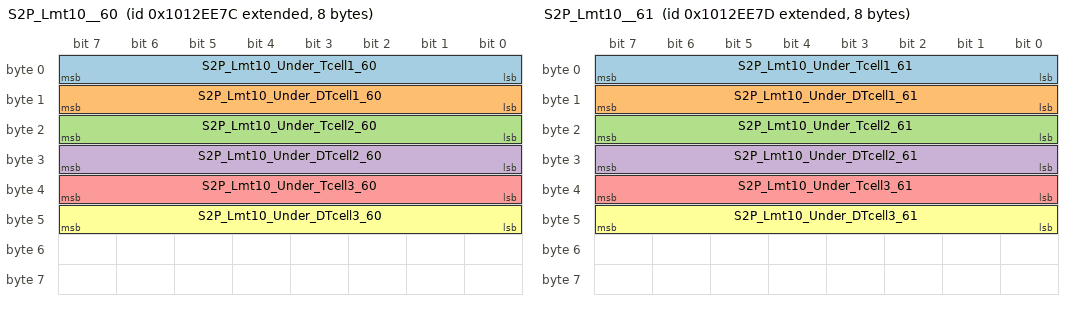
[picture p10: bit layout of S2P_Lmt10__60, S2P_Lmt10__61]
BO_ 2417159804 S2P_Lmt10__60: 8 SBMU
 SG_ S2P_Lmt10_Under_Tcell1_60 : 0|8@1+ (1,-50) [-50|205] "℃"  PC
 SG_ S2P_Lmt10_Under_DTcell1_60 : 8|8@1+ (1,-50) [-50|205] "℃"  PC
 SG_ S2P_Lmt10_Under_Tcell2_60 : 16|8@1+ (1,-50) [-50|205] "℃"  PC
 SG_ S2P_Lmt10_Under_DTcell2_60 : 24|8@1+ (1,-50) [-50|205] "℃"  PC
 SG_ S2P_Lmt10_Under_Tcell3_60 : 32|8@1+ (1,-50) [-50|205] "℃"  PC
 SG_ S2P_Lmt10_Under_DTcell3_60 : 40|8@1+ (1,-50) [-50|205] "℃"  PC

BO_ 2417159805 S2P_Lmt10__61: 8 SBMU
 SG_ S2P_Lmt10_Under_Tcell1_61 : 0|8@1+ (1,-50) [-50|205] "℃"  PC
 SG_ S2P_Lmt10_Under_DTcell1_61 : 8|8@1+ (1,-50) [-50|205] "℃"  PC
 SG_ S2P_Lmt10_Under_Tcell2_61 : 16|8@1+ (1,-50) [-50|205] "℃"  PC
 SG_ S2P_Lmt10_Under_DTcell2_61 : 24|8@1+ (1,-50) [-50|205] "℃"  PC
 SG_ S2P_Lmt10_Under_Tcell3_61 : 32|8@1+ (1,-50) [-50|205] "℃"  PC
 SG_ S2P_Lmt10_Under_DTcell3_61 : 40|8@1+ (1,-50) [-50|205] "℃"  PC

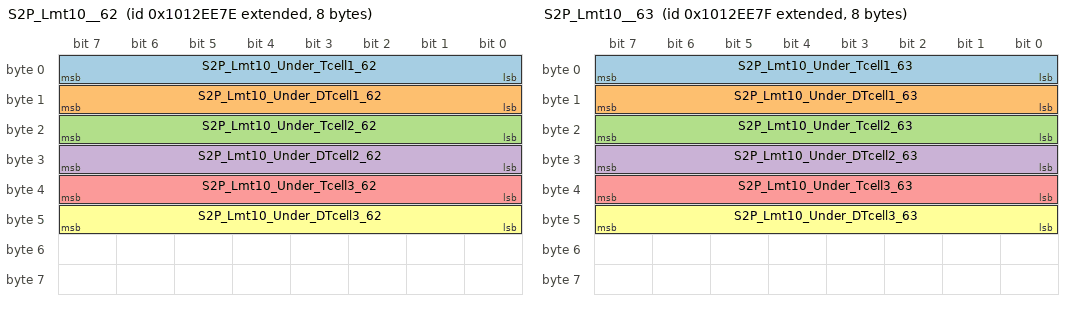
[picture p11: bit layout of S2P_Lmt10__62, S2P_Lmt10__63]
BO_ 2417159806 S2P_Lmt10__62: 8 SBMU
 SG_ S2P_Lmt10_Under_Tcell1_62 : 0|8@1+ (1,-50) [-50|205] "℃"  PC
 SG_ S2P_Lmt10_Under_DTcell1_62 : 8|8@1+ (1,-50) [-50|205] "℃"  PC
 SG_ S2P_Lmt10_Under_Tcell2_62 : 16|8@1+ (1,-50) [-50|205] "℃"  PC
 SG_ S2P_Lmt10_Under_DTcell2_62 : 24|8@1+ (1,-50) [-50|205] "℃"  PC
 SG_ S2P_Lmt10_Under_Tcell3_62 : 32|8@1+ (1,-50) [-50|205] "℃"  PC
 SG_ S2P_Lmt10_Under_DTcell3_62 : 40|8@1+ (1,-50) [-50|205] "℃"  PC

BO_ 2417159807 S2P_Lmt10__63: 8 SBMU
 SG_ S2P_Lmt10_Under_Tcell1_63 : 0|8@1+ (1,-50) [-50|205] "℃"  PC
 SG_ S2P_Lmt10_Under_DTcell1_63 : 8|8@1+ (1,-50) [-50|205] "℃"  PC
 SG_ S2P_Lmt10_Under_Tcell2_63 : 16|8@1+ (1,-50) [-50|205] "℃"  PC
 SG_ S2P_Lmt10_Under_DTcell2_63 : 24|8@1+ (1,-50) [-50|205] "℃"  PC
 SG_ S2P_Lmt10_Under_Tcell3_63 : 32|8@1+ (1,-50) [-50|205] "℃"  PC
 SG_ S2P_Lmt10_Under_DTcell3_63 : 40|8@1+ (1,-50) [-50|205] "℃"  PC

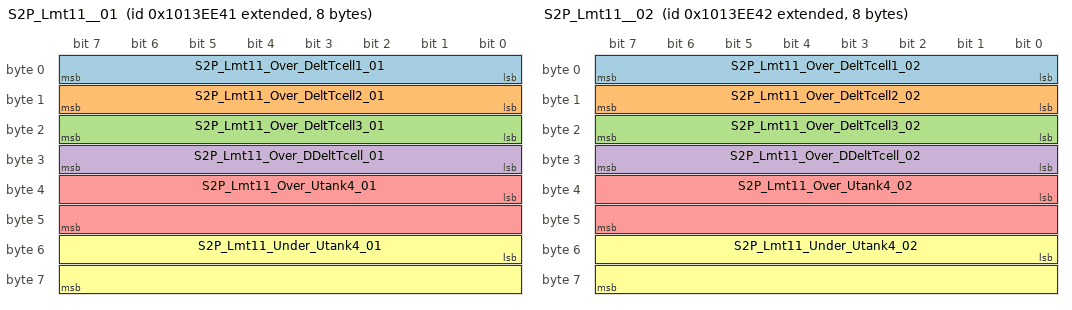
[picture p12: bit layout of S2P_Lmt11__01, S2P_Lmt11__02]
BO_ 2417225281 S2P_Lmt11__01: 8 SBMU
 SG_ S2P_Lmt11_Over_DeltTcell1_01 : 0|8@1+ (1,-50) [-50|205] "℃"  PC
 SG_ S2P_Lmt11_Over_DeltTcell2_01 : 8|8@1+ (1,-50) [-50|205] "℃"  PC
 SG_ S2P_Lmt11_Over_DeltTcell3_01 : 16|8@1+ (1,-50) [-50|205] "℃"  PC
 SG_ S2P_Lmt11_Over_DDeltTcell_01 : 24|8@1+ (1,-50) [-50|205] "℃"  PC
 SG_ S2P_Lmt11_Over_Utank4_01 : 32|16@1+ (0.1,0) [0|6553.5] "V"  PC
 SG_ S2P_Lmt11_Under_Utank4_01 : 48|16@1+ (0.1,0) [0|6553.5] "V"  PC

BO_ 2417225282 S2P_Lmt11__02: 8 SBMU
 SG_ S2P_Lmt11_Over_DeltTcell1_02 : 0|8@1+ (1,-50) [-50|205] "℃"  PC
 SG_ S2P_Lmt11_Over_DeltTcell2_02 : 8|8@1+ (1,-50) [-50|205] "℃"  PC
 SG_ S2P_Lmt11_Over_DeltTcell3_02 : 16|8@1+ (1,-50) [-50|205] "℃"  PC
 SG_ S2P_Lmt11_Over_DDeltTcell_02 : 24|8@1+ (1,-50) [-50|205] "℃"  PC
 SG_ S2P_Lmt11_Over_Utank4_02 : 32|16@1+ (0.1,0) [0|6553.5] "V"  PC
 SG_ S2P_Lmt11_Under_Utank4_02 : 48|16@1+ (0.1,0) [0|6553.5] "V"  PC

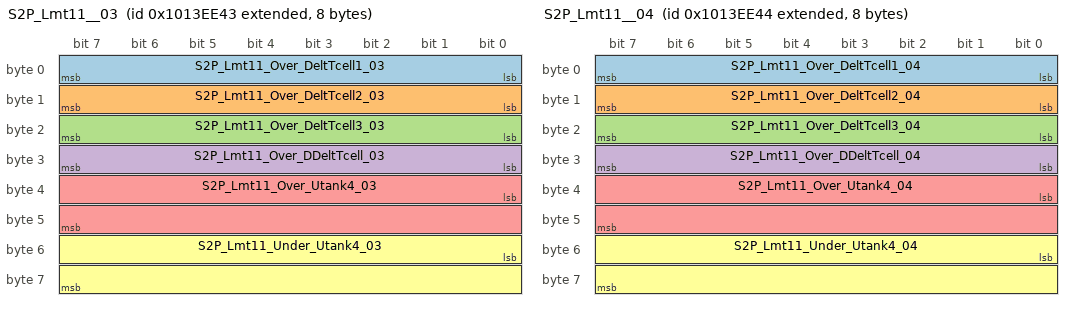
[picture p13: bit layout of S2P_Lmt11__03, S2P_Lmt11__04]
BO_ 2417225283 S2P_Lmt11__03: 8 SBMU
 SG_ S2P_Lmt11_Over_DeltTcell1_03 : 0|8@1+ (1,-50) [-50|205] "℃"  PC
 SG_ S2P_Lmt11_Over_DeltTcell2_03 : 8|8@1+ (1,-50) [-50|205] "℃"  PC
 SG_ S2P_Lmt11_Over_DeltTcell3_03 : 16|8@1+ (1,-50) [-50|205] "℃"  PC
 SG_ S2P_Lmt11_Over_DDeltTcell_03 : 24|8@1+ (1,-50) [-50|205] "℃"  PC
 SG_ S2P_Lmt11_Over_Utank4_03 : 32|16@1+ (0.1,0) [0|6553.5] "V"  PC
 SG_ S2P_Lmt11_Under_Utank4_03 : 48|16@1+ (0.1,0) [0|6553.5] "V"  PC

BO_ 2417225284 S2P_Lmt11__04: 8 SBMU
 SG_ S2P_Lmt11_Over_DeltTcell1_04 : 0|8@1+ (1,-50) [-50|205] "℃"  PC
 SG_ S2P_Lmt11_Over_DeltTcell2_04 : 8|8@1+ (1,-50) [-50|205] "℃"  PC
 SG_ S2P_Lmt11_Over_DeltTcell3_04 : 16|8@1+ (1,-50) [-50|205] "℃"  PC
 SG_ S2P_Lmt11_Over_DDeltTcell_04 : 24|8@1+ (1,-50) [-50|205] "℃"  PC
 SG_ S2P_Lmt11_Over_Utank4_04 : 32|16@1+ (0.1,0) [0|6553.5] "V"  PC
 SG_ S2P_Lmt11_Under_Utank4_04 : 48|16@1+ (0.1,0) [0|6553.5] "V"  PC

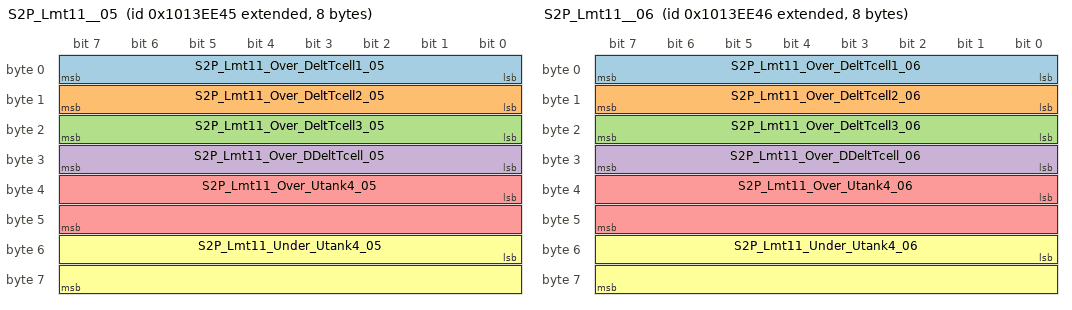
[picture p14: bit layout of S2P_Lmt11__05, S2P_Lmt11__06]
BO_ 2417225285 S2P_Lmt11__05: 8 SBMU
 SG_ S2P_Lmt11_Over_DeltTcell1_05 : 0|8@1+ (1,-50) [-50|205] "℃"  PC
 SG_ S2P_Lmt11_Over_DeltTcell2_05 : 8|8@1+ (1,-50) [-50|205] "℃"  PC
 SG_ S2P_Lmt11_Over_DeltTcell3_05 : 16|8@1+ (1,-50) [-50|205] "℃"  PC
 SG_ S2P_Lmt11_Over_DDeltTcell_05 : 24|8@1+ (1,-50) [-50|205] "℃"  PC
 SG_ S2P_Lmt11_Over_Utank4_05 : 32|16@1+ (0.1,0) [0|6553.5] "V"  PC
 SG_ S2P_Lmt11_Under_Utank4_05 : 48|16@1+ (0.1,0) [0|6553.5] "V"  PC

BO_ 2417225286 S2P_Lmt11__06: 8 SBMU
 SG_ S2P_Lmt11_Over_DeltTcell1_06 : 0|8@1+ (1,-50) [-50|205] "℃"  PC
 SG_ S2P_Lmt11_Over_DeltTcell2_06 : 8|8@1+ (1,-50) [-50|205] "℃"  PC
 SG_ S2P_Lmt11_Over_DeltTcell3_06 : 16|8@1+ (1,-50) [-50|205] "℃"  PC
 SG_ S2P_Lmt11_Over_DDeltTcell_06 : 24|8@1+ (1,-50) [-50|205] "℃"  PC
 SG_ S2P_Lmt11_Over_Utank4_06 : 32|16@1+ (0.1,0) [0|6553.5] "V"  PC
 SG_ S2P_Lmt11_Under_Utank4_06 : 48|16@1+ (0.1,0) [0|6553.5] "V"  PC

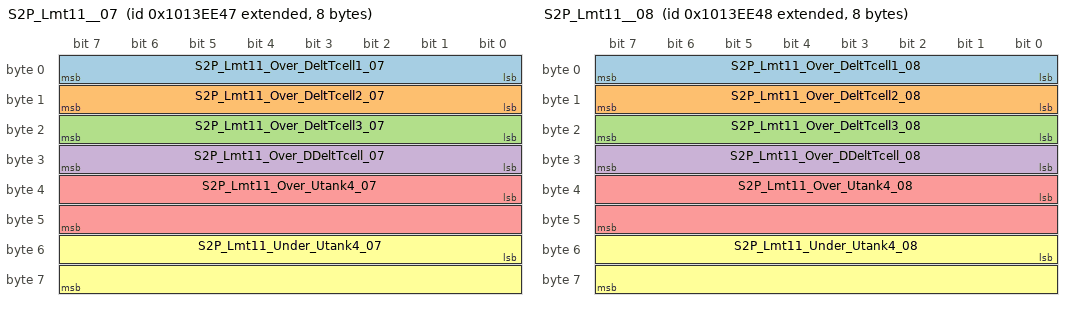
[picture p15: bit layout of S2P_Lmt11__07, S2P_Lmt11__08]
BO_ 2417225287 S2P_Lmt11__07: 8 SBMU
 SG_ S2P_Lmt11_Over_DeltTcell1_07 : 0|8@1+ (1,-50) [-50|205] "℃"  PC
 SG_ S2P_Lmt11_Over_DeltTcell2_07 : 8|8@1+ (1,-50) [-50|205] "℃"  PC
 SG_ S2P_Lmt11_Over_DeltTcell3_07 : 16|8@1+ (1,-50) [-50|205] "℃"  PC
 SG_ S2P_Lmt11_Over_DDeltTcell_07 : 24|8@1+ (1,-50) [-50|205] "℃"  PC
 SG_ S2P_Lmt11_Over_Utank4_07 : 32|16@1+ (0.1,0) [0|6553.5] "V"  PC
 SG_ S2P_Lmt11_Under_Utank4_07 : 48|16@1+ (0.1,0) [0|6553.5] "V"  PC

BO_ 2417225288 S2P_Lmt11__08: 8 SBMU
 SG_ S2P_Lmt11_Over_DeltTcell1_08 : 0|8@1+ (1,-50) [-50|205] "℃"  PC
 SG_ S2P_Lmt11_Over_DeltTcell2_08 : 8|8@1+ (1,-50) [-50|205] "℃"  PC
 SG_ S2P_Lmt11_Over_DeltTcell3_08 : 16|8@1+ (1,-50) [-50|205] "℃"  PC
 SG_ S2P_Lmt11_Over_DDeltTcell_08 : 24|8@1+ (1,-50) [-50|205] "℃"  PC
 SG_ S2P_Lmt11_Over_Utank4_08 : 32|16@1+ (0.1,0) [0|6553.5] "V"  PC
 SG_ S2P_Lmt11_Under_Utank4_08 : 48|16@1+ (0.1,0) [0|6553.5] "V"  PC

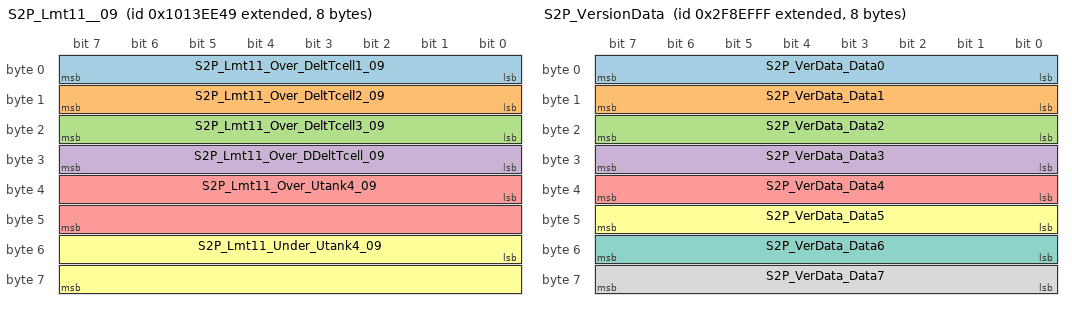
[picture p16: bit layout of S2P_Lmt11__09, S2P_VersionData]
BO_ 2417225289 S2P_Lmt11__09: 8 SBMU
 SG_ S2P_Lmt11_Over_DeltTcell1_09 : 0|8@1+ (1,-50) [-50|205] "℃"  PC
 SG_ S2P_Lmt11_Over_DeltTcell2_09 : 8|8@1+ (1,-50) [-50|205] "℃"  PC
 SG_ S2P_Lmt11_Over_DeltTcell3_09 : 16|8@1+ (1,-50) [-50|205] "℃"  PC
 SG_ S2P_Lmt11_Over_DDeltTcell_09 : 24|8@1+ (1,-50) [-50|205] "℃"  PC
 SG_ S2P_Lmt11_Over_Utank4_09 : 32|16@1+ (0.1,0) [0|6553.5] "V"  PC
 SG_ S2P_Lmt11_Under_Utank4_09 : 48|16@1+ (0.1,0) [0|6553.5] "V"  PC

BO_ 2417225290 S2P_Lmt11__10: 8 SBMU
 SG_ S2P_Lmt11_Over_DeltTcell1_10 : 0|8@1+ (1,-50) [-50|205] "℃"  PC
 SG_ S2P_Lmt11_Over_DeltTcell2_10 : 8|8@1+ (1,-50) [-50|205] "℃"  PC
 SG_ S2P_Lmt11_Over_DeltTcell3_10 : 16|8@1+ (1,-50) [-50|205] "℃"  PC
 SG_ S2P_Lmt11_Over_DDeltTcell_10 : 24|8@1+ (1,-50) [-50|205] "℃"  PC
 SG_ S2P_Lmt11_Over_Utank4_10 : 32|16@1+ (0.1,0) [0|6553.5] "V"  PC
 SG_ S2P_Lmt11_Under_Utank4_10 : 48|16@1+ (0.1,0) [0|6553.5] "V"  PC

BO_ 2417225291 S2P_Lmt11__11: 8 SBMU
 SG_ S2P_Lmt11_Over_DeltTcell1_11 : 0|8@1+ (1,-50) [-50|205] "℃"  PC
 SG_ S2P_Lmt11_Over_DeltTcell2_11 : 8|8@1+ (1,-50) [-50|205] "℃"  PC
 SG_ S2P_Lmt11_Over_DeltTcell3_11 : 16|8@1+ (1,-50) [-50|205] "℃"  PC
 SG_ S2P_Lmt11_Over_DDeltTcell_11 : 24|8@1+ (1,-50) [-50|205] "℃"  PC
 SG_ S2P_Lmt11_Over_Utank4_11 : 32|16@1+ (0.1,0) [0|6553.5] "V"  PC
 SG_ S2P_Lmt11_Under_Utank4_11 : 48|16@1+ (0.1,0) [0|6553.5] "V"  PC

BO_ 2417225292 S2P_Lmt11__12: 8 SBMU
 SG_ S2P_Lmt11_Over_DeltTcell1_12 : 0|8@1+ (1,-50) [-50|205] "℃"  PC
 SG_ S2P_Lmt11_Over_DeltTcell2_12 : 8|8@1+ (1,-50) [-50|205] "℃"  PC
 SG_ S2P_Lmt11_Over_DeltTcell3_12 : 16|8@1+ (1,-50) [-50|205] "℃"  PC
 SG_ S2P_Lmt11_Over_DDeltTcell_12 : 24|8@1+ (1,-50) [-50|205] "℃"  PC
 SG_ S2P_Lmt11_Over_Utank4_12 : 32|16@1+ (0.1,0) [0|6553.5] "V"  PC
 SG_ S2P_Lmt11_Under_Utank4_12 : 48|16@1+ (0.1,0) [0|6553.5] "V"  PC

BO_ 2417225293 S2P_Lmt11__13: 8 SBMU
 SG_ S2P_Lmt11_Over_DeltTcell1_13 : 0|8@1+ (1,-50) [-50|205] "℃"  PC
 SG_ S2P_Lmt11_Over_DeltTcell2_13 : 8|8@1+ (1,-50) [-50|205] "℃"  PC
 SG_ S2P_Lmt11_Over_DeltTcell3_13 : 16|8@1+ (1,-50) [-50|205] "℃"  PC
 SG_ S2P_Lmt11_Over_DDeltTcell_13 : 24|8@1+ (1,-50) [-50|205] "℃"  PC
 SG_ S2P_Lmt11_Over_Utank4_13 : 32|16@1+ (0.1,0) [0|6553.5] "V"  PC
 SG_ S2P_Lmt11_Under_Utank4_13 : 48|16@1+ (0.1,0) [0|6553.5] "V"  PC

BO_ 2417225294 S2P_Lmt11__14: 8 SBMU
 SG_ S2P_Lmt11_Over_DeltTcell1_14 : 0|8@1+ (1,-50) [-50|205] "℃"  PC
 SG_ S2P_Lmt11_Over_DeltTcell2_14 : 8|8@1+ (1,-50) [-50|205] "℃"  PC
 SG_ S2P_Lmt11_Over_DeltTcell3_14 : 16|8@1+ (1,-50) [-50|205] "℃"  PC
 SG_ S2P_Lmt11_Over_DDeltTcell_14 : 24|8@1+ (1,-50) [-50|205] "℃"  PC
 SG_ S2P_Lmt11_Over_Utank4_14 : 32|16@1+ (0.1,0) [0|6553.5] "V"  PC
 SG_ S2P_Lmt11_Under_Utank4_14 : 48|16@1+ (0.1,0) [0|6553.5] "V"  PC

BO_ 2417225295 S2P_Lmt11__15: 8 SBMU
 SG_ S2P_Lmt11_Over_DeltTcell1_15 : 0|8@1+ (1,-50) [-50|205] "℃"  PC
 SG_ S2P_Lmt11_Over_DeltTcell2_15 : 8|8@1+ (1,-50) [-50|205] "℃"  PC
 SG_ S2P_Lmt11_Over_DeltTcell3_15 : 16|8@1+ (1,-50) [-50|205] "℃"  PC
 SG_ S2P_Lmt11_Over_DDeltTcell_15 : 24|8@1+ (1,-50) [-50|205] "℃"  PC
 SG_ S2P_Lmt11_Over_Utank4_15 : 32|16@1+ (0.1,0) [0|6553.5] "V"  PC
 SG_ S2P_Lmt11_Under_Utank4_15 : 48|16@1+ (0.1,0) [0|6553.5] "V"  PC

BO_ 2417225296 S2P_Lmt11__16: 8 SBMU
 SG_ S2P_Lmt11_Over_DeltTcell1_16 : 0|8@1+ (1,-50) [-50|205] "℃"  PC
 SG_ S2P_Lmt11_Over_DeltTcell2_16 : 8|8@1+ (1,-50) [-50|205] "℃"  PC
 SG_ S2P_Lmt11_Over_DeltTcell3_16 : 16|8@1+ (1,-50) [-50|205] "℃"  PC
 SG_ S2P_Lmt11_Over_DDeltTcell_16 : 24|8@1+ (1,-50) [-50|205] "℃"  PC
 SG_ S2P_Lmt11_Over_Utank4_16 : 32|16@1+ (0.1,0) [0|6553.5] "V"  PC
 SG_ S2P_Lmt11_Under_Utank4_16 : 48|16@1+ (0.1,0) [0|6553.5] "V"  PC

BO_ 2417225297 S2P_Lmt11__17: 8 SBMU
 SG_ S2P_Lmt11_Over_DeltTcell1_17 : 0|8@1+ (1,-50) [-50|205] "℃"  PC
 SG_ S2P_Lmt11_Over_DeltTcell2_17 : 8|8@1+ (1,-50) [-50|205] "℃"  PC
 SG_ S2P_Lmt11_Over_DeltTcell3_17 : 16|8@1+ (1,-50) [-50|205] "℃"  PC
 SG_ S2P_Lmt11_Over_DDeltTcell_17 : 24|8@1+ (1,-50) [-50|205] "℃"  PC
 SG_ S2P_Lmt11_Over_Utank4_17 : 32|16@1+ (0.1,0) [0|6553.5] "V"  PC
 SG_ S2P_Lmt11_Under_Utank4_17 : 48|16@1+ (0.1,0) [0|6553.5] "V"  PC

BO_ 2417225298 S2P_Lmt11__18: 8 SBMU
 SG_ S2P_Lmt11_Over_DeltTcell1_18 : 0|8@1+ (1,-50) [-50|205] "℃"  PC
 SG_ S2P_Lmt11_Over_DeltTcell2_18 : 8|8@1+ (1,-50) [-50|205] "℃"  PC
 SG_ S2P_Lmt11_Over_DeltTcell3_18 : 16|8@1+ (1,-50) [-50|205] "℃"  PC
 SG_ S2P_Lmt11_Over_DDeltTcell_18 : 24|8@1+ (1,-50) [-50|205] "℃"  PC
 SG_ S2P_Lmt11_Over_Utank4_18 : 32|16@1+ (0.1,0) [0|6553.5] "V"  PC
 SG_ S2P_Lmt11_Under_Utank4_18 : 48|16@1+ (0.1,0) [0|6553.5] "V"  PC

BO_ 2417225299 S2P_Lmt11__19: 8 SBMU
 SG_ S2P_Lmt11_Over_DeltTcell1_19 : 0|8@1+ (1,-50) [-50|205] "℃"  PC
 SG_ S2P_Lmt11_Over_DeltTcell2_19 : 8|8@1+ (1,-50) [-50|205] "℃"  PC
 SG_ S2P_Lmt11_Over_DeltTcell3_19 : 16|8@1+ (1,-50) [-50|205] "℃"  PC
 SG_ S2P_Lmt11_Over_DDeltTcell_19 : 24|8@1+ (1,-50) [-50|205] "℃"  PC
 SG_ S2P_Lmt11_Over_Utank4_19 : 32|16@1+ (0.1,0) [0|6553.5] "V"  PC
 SG_ S2P_Lmt11_Under_Utank4_19 : 48|16@1+ (0.1,0) [0|6553.5] "V"  PC

BO_ 2417225300 S2P_Lmt11__20: 8 SBMU
 SG_ S2P_Lmt11_Over_DeltTcell1_20 : 0|8@1+ (1,-50) [-50|205] "℃"  PC
 SG_ S2P_Lmt11_Over_DeltTcell2_20 : 8|8@1+ (1,-50) [-50|205] "℃"  PC
 SG_ S2P_Lmt11_Over_DeltTcell3_20 : 16|8@1+ (1,-50) [-50|205] "℃"  PC
 SG_ S2P_Lmt11_Over_DDeltTcell_20 : 24|8@1+ (1,-50) [-50|205] "℃"  PC
 SG_ S2P_Lmt11_Over_Utank4_20 : 32|16@1+ (0.1,0) [0|6553.5] "V"  PC
 SG_ S2P_Lmt11_Under_Utank4_20 : 48|16@1+ (0.1,0) [0|6553.5] "V"  PC

BO_ 2417225301 S2P_Lmt11__21: 8 SBMU
 SG_ S2P_Lmt11_Over_DeltTcell1_21 : 0|8@1+ (1,-50) [-50|205] "℃"  PC
 SG_ S2P_Lmt11_Over_DeltTcell2_21 : 8|8@1+ (1,-50) [-50|205] "℃"  PC
 SG_ S2P_Lmt11_Over_DeltTcell3_21 : 16|8@1+ (1,-50) [-50|205] "℃"  PC
 SG_ S2P_Lmt11_Over_DDeltTcell_21 : 24|8@1+ (1,-50) [-50|205] "℃"  PC
 SG_ S2P_Lmt11_Over_Utank4_21 : 32|16@1+ (0.1,0) [0|6553.5] "V"  PC
 SG_ S2P_Lmt11_Under_Utank4_21 : 48|16@1+ (0.1,0) [0|6553.5] "V"  PC

BO_ 2417225302 S2P_Lmt11__22: 8 SBMU
 SG_ S2P_Lmt11_Over_DeltTcell1_22 : 0|8@1+ (1,-50) [-50|205] "℃"  PC
 SG_ S2P_Lmt11_Over_DeltTcell2_22 : 8|8@1+ (1,-50) [-50|205] "℃"  PC
 SG_ S2P_Lmt11_Over_DeltTcell3_22 : 16|8@1+ (1,-50) [-50|205] "℃"  PC
 SG_ S2P_Lmt11_Over_DDeltTcell_22 : 24|8@1+ (1,-50) [-50|205] "℃"  PC
 SG_ S2P_Lmt11_Over_Utank4_22 : 32|16@1+ (0.1,0) [0|6553.5] "V"  PC
 SG_ S2P_Lmt11_Under_Utank4_22 : 48|16@1+ (0.1,0) [0|6553.5] "V"  PC

BO_ 2417225303 S2P_Lmt11__23: 8 SBMU
 SG_ S2P_Lmt11_Over_DeltTcell1_23 : 0|8@1+ (1,-50) [-50|205] "℃"  PC
 SG_ S2P_Lmt11_Over_DeltTcell2_23 : 8|8@1+ (1,-50) [-50|205] "℃"  PC
 SG_ S2P_Lmt11_Over_DeltTcell3_23 : 16|8@1+ (1,-50) [-50|205] "℃"  PC
 SG_ S2P_Lmt11_Over_DDeltTcell_23 : 24|8@1+ (1,-50) [-50|205] "℃"  PC
 SG_ S2P_Lmt11_Over_Utank4_23 : 32|16@1+ (0.1,0) [0|6553.5] "V"  PC
 SG_ S2P_Lmt11_Under_Utank4_23 : 48|16@1+ (0.1,0) [0|6553.5] "V"  PC

BO_ 2417225304 S2P_Lmt11__24: 8 SBMU
 SG_ S2P_Lmt11_Over_DeltTcell1_24 : 0|8@1+ (1,-50) [-50|205] "℃"  PC
 SG_ S2P_Lmt11_Over_DeltTcell2_24 : 8|8@1+ (1,-50) [-50|205] "℃"  PC
 SG_ S2P_Lmt11_Over_DeltTcell3_24 : 16|8@1+ (1,-50) [-50|205] "℃"  PC
 SG_ S2P_Lmt11_Over_DDeltTcell_24 : 24|8@1+ (1,-50) [-50|205] "℃"  PC
 SG_ S2P_Lmt11_Over_Utank4_24 : 32|16@1+ (0.1,0) [0|6553.5] "V"  PC
 SG_ S2P_Lmt11_Under_Utank4_24 : 48|16@1+ (0.1,0) [0|6553.5] "V"  PC

BO_ 2417225305 S2P_Lmt11__25: 8 SBMU
 SG_ S2P_Lmt11_Over_DeltTcell1_25 : 0|8@1+ (1,-50) [-50|205] "℃"  PC
 SG_ S2P_Lmt11_Over_DeltTcell2_25 : 8|8@1+ (1,-50) [-50|205] "℃"  PC
 SG_ S2P_Lmt11_Over_DeltTcell3_25 : 16|8@1+ (1,-50) [-50|205] "℃"  PC
 SG_ S2P_Lmt11_Over_DDeltTcell_25 : 24|8@1+ (1,-50) [-50|205] "℃"  PC
 SG_ S2P_Lmt11_Over_Utank4_25 : 32|16@1+ (0.1,0) [0|6553.5] "V"  PC
 SG_ S2P_Lmt11_Under_Utank4_25 : 48|16@1+ (0.1,0) [0|6553.5] "V"  PC

BO_ 2417225306 S2P_Lmt11__26: 8 SBMU
 SG_ S2P_Lmt11_Over_DeltTcell1_26 : 0|8@1+ (1,-50) [-50|205] "℃"  PC
 SG_ S2P_Lmt11_Over_DeltTcell2_26 : 8|8@1+ (1,-50) [-50|205] "℃"  PC
 SG_ S2P_Lmt11_Over_DeltTcell3_26 : 16|8@1+ (1,-50) [-50|205] "℃"  PC
 SG_ S2P_Lmt11_Over_DDeltTcell_26 : 24|8@1+ (1,-50) [-50|205] "℃"  PC
 SG_ S2P_Lmt11_Over_Utank4_26 : 32|16@1+ (0.1,0) [0|6553.5] "V"  PC
 SG_ S2P_Lmt11_Under_Utank4_26 : 48|16@1+ (0.1,0) [0|6553.5] "V"  PC

BO_ 2417225307 S2P_Lmt11__27: 8 SBMU
 SG_ S2P_Lmt11_Over_DeltTcell1_27 : 0|8@1+ (1,-50) [-50|205] "℃"  PC
 SG_ S2P_Lmt11_Over_DeltTcell2_27 : 8|8@1+ (1,-50) [-50|205] "℃"  PC
 SG_ S2P_Lmt11_Over_DeltTcell3_27 : 16|8@1+ (1,-50) [-50|205] "℃"  PC
 SG_ S2P_Lmt11_Over_DDeltTcell_27 : 24|8@1+ (1,-50) [-50|205] "℃"  PC
 SG_ S2P_Lmt11_Over_Utank4_27 : 32|16@1+ (0.1,0) [0|6553.5] "V"  PC
 SG_ S2P_Lmt11_Under_Utank4_27 : 48|16@1+ (0.1,0) [0|6553.5] "V"  PC

BO_ 2417225308 S2P_Lmt11__28: 8 SBMU
 SG_ S2P_Lmt11_Over_DeltTcell1_28 : 0|8@1+ (1,-50) [-50|205] "℃"  PC
 SG_ S2P_Lmt11_Over_DeltTcell2_28 : 8|8@1+ (1,-50) [-50|205] "℃"  PC
 SG_ S2P_Lmt11_Over_DeltTcell3_28 : 16|8@1+ (1,-50) [-50|205] "℃"  PC
 SG_ S2P_Lmt11_Over_DDeltTcell_28 : 24|8@1+ (1,-50) [-50|205] "℃"  PC
 SG_ S2P_Lmt11_Over_Utank4_28 : 32|16@1+ (0.1,0) [0|6553.5] "V"  PC
 SG_ S2P_Lmt11_Under_Utank4_28 : 48|16@1+ (0.1,0) [0|6553.5] "V"  PC

BO_ 2417225309 S2P_Lmt11__29: 8 SBMU
 SG_ S2P_Lmt11_Over_DeltTcell1_29 : 0|8@1+ (1,-50) [-50|205] "℃"  PC
 SG_ S2P_Lmt11_Over_DeltTcell2_29 : 8|8@1+ (1,-50) [-50|205] "℃"  PC
 SG_ S2P_Lmt11_Over_DeltTcell3_29 : 16|8@1+ (1,-50) [-50|205] "℃"  PC
 SG_ S2P_Lmt11_Over_DDeltTcell_29 : 24|8@1+ (1,-50) [-50|205] "℃"  PC
 SG_ S2P_Lmt11_Over_Utank4_29 : 32|16@1+ (0.1,0) [0|6553.5] "V"  PC
 SG_ S2P_Lmt11_Under_Utank4_29 : 48|16@1+ (0.1,0) [0|6553.5] "V"  PC

BO_ 2417225310 S2P_Lmt11__30: 8 SBMU
 SG_ S2P_Lmt11_Over_DeltTcell1_30 : 0|8@1+ (1,-50) [-50|205] "℃"  PC
 SG_ S2P_Lmt11_Over_DeltTcell2_30 : 8|8@1+ (1,-50) [-50|205] "℃"  PC
 SG_ S2P_Lmt11_Over_DeltTcell3_30 : 16|8@1+ (1,-50) [-50|205] "℃"  PC
 SG_ S2P_Lmt11_Over_DDeltTcell_30 : 24|8@1+ (1,-50) [-50|205] "℃"  PC
 SG_ S2P_Lmt11_Over_Utank4_30 : 32|16@1+ (0.1,0) [0|6553.5] "V"  PC
 SG_ S2P_Lmt11_Under_Utank4_30 : 48|16@1+ (0.1,0) [0|6553.5] "V"  PC

BO_ 2417225311 S2P_Lmt11__31: 8 SBMU
 SG_ S2P_Lmt11_Over_DeltTcell1_31 : 0|8@1+ (1,-50) [-50|205] "℃"  PC
 SG_ S2P_Lmt11_Over_DeltTcell2_31 : 8|8@1+ (1,-50) [-50|205] "℃"  PC
 SG_ S2P_Lmt11_Over_DeltTcell3_31 : 16|8@1+ (1,-50) [-50|205] "℃"  PC
 SG_ S2P_Lmt11_Over_DDeltTcell_31 : 24|8@1+ (1,-50) [-50|205] "℃"  PC
 SG_ S2P_Lmt11_Over_Utank4_31 : 32|16@1+ (0.1,0) [0|6553.5] "V"  PC
 SG_ S2P_Lmt11_Under_Utank4_31 : 48|16@1+ (0.1,0) [0|6553.5] "V"  PC

BO_ 2417225312 S2P_Lmt11__32: 8 SBMU
 SG_ S2P_Lmt11_Over_DeltTcell1_32 : 0|8@1+ (1,-50) [-50|205] "℃"  PC
 SG_ S2P_Lmt11_Over_DeltTcell2_32 : 8|8@1+ (1,-50) [-50|205] "℃"  PC
 SG_ S2P_Lmt11_Over_DeltTcell3_32 : 16|8@1+ (1,-50) [-50|205] "℃"  PC
 SG_ S2P_Lmt11_Over_DDeltTcell_32 : 24|8@1+ (1,-50) [-50|205] "℃"  PC
 SG_ S2P_Lmt11_Over_Utank4_32 : 32|16@1+ (0.1,0) [0|6553.5] "V"  PC
 SG_ S2P_Lmt11_Under_Utank4_32 : 48|16@1+ (0.1,0) [0|6553.5] "V"  PC

BO_ 2417225313 S2P_Lmt11__33: 8 SBMU
 SG_ S2P_Lmt11_Over_DeltTcell1_33 : 0|8@1+ (1,-50) [-50|205] "℃"  PC
 SG_ S2P_Lmt11_Over_DeltTcell2_33 : 8|8@1+ (1,-50) [-50|205] "℃"  PC
 SG_ S2P_Lmt11_Over_DeltTcell3_33 : 16|8@1+ (1,-50) [-50|205] "℃"  PC
 SG_ S2P_Lmt11_Over_DDeltTcell_33 : 24|8@1+ (1,-50) [-50|205] "℃"  PC
 SG_ S2P_Lmt11_Over_Utank4_33 : 32|16@1+ (0.1,0) [0|6553.5] "V"  PC
 SG_ S2P_Lmt11_Under_Utank4_33 : 48|16@1+ (0.1,0) [0|6553.5] "V"  PC

BO_ 2417225314 S2P_Lmt11__34: 8 SBMU
 SG_ S2P_Lmt11_Over_DeltTcell1_34 : 0|8@1+ (1,-50) [-50|205] "℃"  PC
 SG_ S2P_Lmt11_Over_DeltTcell2_34 : 8|8@1+ (1,-50) [-50|205] "℃"  PC
 SG_ S2P_Lmt11_Over_DeltTcell3_34 : 16|8@1+ (1,-50) [-50|205] "℃"  PC
 SG_ S2P_Lmt11_Over_DDeltTcell_34 : 24|8@1+ (1,-50) [-50|205] "℃"  PC
 SG_ S2P_Lmt11_Over_Utank4_34 : 32|16@1+ (0.1,0) [0|6553.5] "V"  PC
 SG_ S2P_Lmt11_Under_Utank4_34 : 48|16@1+ (0.1,0) [0|6553.5] "V"  PC

BO_ 2417225315 S2P_Lmt11__35: 8 SBMU
 SG_ S2P_Lmt11_Over_DeltTcell1_35 : 0|8@1+ (1,-50) [-50|205] "℃"  PC
 SG_ S2P_Lmt11_Over_DeltTcell2_35 : 8|8@1+ (1,-50) [-50|205] "℃"  PC
 SG_ S2P_Lmt11_Over_DeltTcell3_35 : 16|8@1+ (1,-50) [-50|205] "℃"  PC
 SG_ S2P_Lmt11_Over_DDeltTcell_35 : 24|8@1+ (1,-50) [-50|205] "℃"  PC
 SG_ S2P_Lmt11_Over_Utank4_35 : 32|16@1+ (0.1,0) [0|6553.5] "V"  PC
 SG_ S2P_Lmt11_Under_Utank4_35 : 48|16@1+ (0.1,0) [0|6553.5] "V"  PC

BO_ 2417225316 S2P_Lmt11__36: 8 SBMU
 SG_ S2P_Lmt11_Over_DeltTcell1_36 : 0|8@1+ (1,-50) [-50|205] "℃"  PC
 SG_ S2P_Lmt11_Over_DeltTcell2_36 : 8|8@1+ (1,-50) [-50|205] "℃"  PC
 SG_ S2P_Lmt11_Over_DeltTcell3_36 : 16|8@1+ (1,-50) [-50|205] "℃"  PC
 SG_ S2P_Lmt11_Over_DDeltTcell_36 : 24|8@1+ (1,-50) [-50|205] "℃"  PC
 SG_ S2P_Lmt11_Over_Utank4_36 : 32|16@1+ (0.1,0) [0|6553.5] "V"  PC
 SG_ S2P_Lmt11_Under_Utank4_36 : 48|16@1+ (0.1,0) [0|6553.5] "V"  PC

BO_ 2417225317 S2P_Lmt11__37: 8 SBMU
 SG_ S2P_Lmt11_Over_DeltTcell1_37 : 0|8@1+ (1,-50) [-50|205] "℃"  PC
 SG_ S2P_Lmt11_Over_DeltTcell2_37 : 8|8@1+ (1,-50) [-50|205] "℃"  PC
 SG_ S2P_Lmt11_Over_DeltTcell3_37 : 16|8@1+ (1,-50) [-50|205] "℃"  PC
 SG_ S2P_Lmt11_Over_DDeltTcell_37 : 24|8@1+ (1,-50) [-50|205] "℃"  PC
 SG_ S2P_Lmt11_Over_Utank4_37 : 32|16@1+ (0.1,0) [0|6553.5] "V"  PC
 SG_ S2P_Lmt11_Under_Utank4_37 : 48|16@1+ (0.1,0) [0|6553.5] "V"  PC

BO_ 2417225318 S2P_Lmt11__38: 8 SBMU
 SG_ S2P_Lmt11_Over_DeltTcell1_38 : 0|8@1+ (1,-50) [-50|205] "℃"  PC
 SG_ S2P_Lmt11_Over_DeltTcell2_38 : 8|8@1+ (1,-50) [-50|205] "℃"  PC
 SG_ S2P_Lmt11_Over_DeltTcell3_38 : 16|8@1+ (1,-50) [-50|205] "℃"  PC
 SG_ S2P_Lmt11_Over_DDeltTcell_38 : 24|8@1+ (1,-50) [-50|205] "℃"  PC
 SG_ S2P_Lmt11_Over_Utank4_38 : 32|16@1+ (0.1,0) [0|6553.5] "V"  PC
 SG_ S2P_Lmt11_Under_Utank4_38 : 48|16@1+ (0.1,0) [0|6553.5] "V"  PC

BO_ 2417225319 S2P_Lmt11__39: 8 SBMU
 SG_ S2P_Lmt11_Over_DeltTcell1_39 : 0|8@1+ (1,-50) [-50|205] "℃"  PC
 SG_ S2P_Lmt11_Over_DeltTcell2_39 : 8|8@1+ (1,-50) [-50|205] "℃"  PC
 SG_ S2P_Lmt11_Over_DeltTcell3_39 : 16|8@1+ (1,-50) [-50|205] "℃"  PC
 SG_ S2P_Lmt11_Over_DDeltTcell_39 : 24|8@1+ (1,-50) [-50|205] "℃"  PC
 SG_ S2P_Lmt11_Over_Utank4_39 : 32|16@1+ (0.1,0) [0|6553.5] "V"  PC
 SG_ S2P_Lmt11_Under_Utank4_39 : 48|16@1+ (0.1,0) [0|6553.5] "V"  PC

BO_ 2417225320 S2P_Lmt11__40: 8 SBMU
 SG_ S2P_Lmt11_Over_DeltTcell1_40 : 0|8@1+ (1,-50) [-50|205] "℃"  PC
 SG_ S2P_Lmt11_Over_DeltTcell2_40 : 8|8@1+ (1,-50) [-50|205] "℃"  PC
 SG_ S2P_Lmt11_Over_DeltTcell3_40 : 16|8@1+ (1,-50) [-50|205] "℃"  PC
 SG_ S2P_Lmt11_Over_DDeltTcell_40 : 24|8@1+ (1,-50) [-50|205] "℃"  PC
 SG_ S2P_Lmt11_Over_Utank4_40 : 32|16@1+ (0.1,0) [0|6553.5] "V"  PC
 SG_ S2P_Lmt11_Under_Utank4_40 : 48|16@1+ (0.1,0) [0|6553.5] "V"  PC

BO_ 2417225321 S2P_Lmt11__41: 8 SBMU
 SG_ S2P_Lmt11_Over_DeltTcell1_41 : 0|8@1+ (1,-50) [-50|205] "℃"  PC
 SG_ S2P_Lmt11_Over_DeltTcell2_41 : 8|8@1+ (1,-50) [-50|205] "℃"  PC
 SG_ S2P_Lmt11_Over_DeltTcell3_41 : 16|8@1+ (1,-50) [-50|205] "℃"  PC
 SG_ S2P_Lmt11_Over_DDeltTcell_41 : 24|8@1+ (1,-50) [-50|205] "℃"  PC
 SG_ S2P_Lmt11_Over_Utank4_41 : 32|16@1+ (0.1,0) [0|6553.5] "V"  PC
 SG_ S2P_Lmt11_Under_Utank4_41 : 48|16@1+ (0.1,0) [0|6553.5] "V"  PC

BO_ 2417225322 S2P_Lmt11__42: 8 SBMU
 SG_ S2P_Lmt11_Over_DeltTcell1_42 : 0|8@1+ (1,-50) [-50|205] "℃"  PC
 SG_ S2P_Lmt11_Over_DeltTcell2_42 : 8|8@1+ (1,-50) [-50|205] "℃"  PC
 SG_ S2P_Lmt11_Over_DeltTcell3_42 : 16|8@1+ (1,-50) [-50|205] "℃"  PC
 SG_ S2P_Lmt11_Over_DDeltTcell_42 : 24|8@1+ (1,-50) [-50|205] "℃"  PC
 SG_ S2P_Lmt11_Over_Utank4_42 : 32|16@1+ (0.1,0) [0|6553.5] "V"  PC
 SG_ S2P_Lmt11_Under_Utank4_42 : 48|16@1+ (0.1,0) [0|6553.5] "V"  PC

BO_ 2417225323 S2P_Lmt11__43: 8 SBMU
 SG_ S2P_Lmt11_Over_DeltTcell1_43 : 0|8@1+ (1,-50) [-50|205] "℃"  PC
 SG_ S2P_Lmt11_Over_DeltTcell2_43 : 8|8@1+ (1,-50) [-50|205] "℃"  PC
 SG_ S2P_Lmt11_Over_DeltTcell3_43 : 16|8@1+ (1,-50) [-50|205] "℃"  PC
 SG_ S2P_Lmt11_Over_DDeltTcell_43 : 24|8@1+ (1,-50) [-50|205] "℃"  PC
 SG_ S2P_Lmt11_Over_Utank4_43 : 32|16@1+ (0.1,0) [0|6553.5] "V"  PC
 SG_ S2P_Lmt11_Under_Utank4_43 : 48|16@1+ (0.1,0) [0|6553.5] "V"  PC

BO_ 2417225324 S2P_Lmt11__44: 8 SBMU
 SG_ S2P_Lmt11_Over_DeltTcell1_44 : 0|8@1+ (1,-50) [-50|205] "℃"  PC
 SG_ S2P_Lmt11_Over_DeltTcell2_44 : 8|8@1+ (1,-50) [-50|205] "℃"  PC
 SG_ S2P_Lmt11_Over_DeltTcell3_44 : 16|8@1+ (1,-50) [-50|205] "℃"  PC
 SG_ S2P_Lmt11_Over_DDeltTcell_44 : 24|8@1+ (1,-50) [-50|205] "℃"  PC
 SG_ S2P_Lmt11_Over_Utank4_44 : 32|16@1+ (0.1,0) [0|6553.5] "V"  PC
 SG_ S2P_Lmt11_Under_Utank4_44 : 48|16@1+ (0.1,0) [0|6553.5] "V"  PC

BO_ 2417225325 S2P_Lmt11__45: 8 SBMU
 SG_ S2P_Lmt11_Over_DeltTcell1_45 : 0|8@1+ (1,-50) [-50|205] "℃"  PC
 SG_ S2P_Lmt11_Over_DeltTcell2_45 : 8|8@1+ (1,-50) [-50|205] "℃"  PC
 SG_ S2P_Lmt11_Over_DeltTcell3_45 : 16|8@1+ (1,-50) [-50|205] "℃"  PC
 SG_ S2P_Lmt11_Over_DDeltTcell_45 : 24|8@1+ (1,-50) [-50|205] "℃"  PC
 SG_ S2P_Lmt11_Over_Utank4_45 : 32|16@1+ (0.1,0) [0|6553.5] "V"  PC
 SG_ S2P_Lmt11_Under_Utank4_45 : 48|16@1+ (0.1,0) [0|6553.5] "V"  PC

BO_ 2417225326 S2P_Lmt11__46: 8 SBMU
 SG_ S2P_Lmt11_Over_DeltTcell1_46 : 0|8@1+ (1,-50) [-50|205] "℃"  PC
 SG_ S2P_Lmt11_Over_DeltTcell2_46 : 8|8@1+ (1,-50) [-50|205] "℃"  PC
 SG_ S2P_Lmt11_Over_DeltTcell3_46 : 16|8@1+ (1,-50) [-50|205] "℃"  PC
 SG_ S2P_Lmt11_Over_DDeltTcell_46 : 24|8@1+ (1,-50) [-50|205] "℃"  PC
 SG_ S2P_Lmt11_Over_Utank4_46 : 32|16@1+ (0.1,0) [0|6553.5] "V"  PC
 SG_ S2P_Lmt11_Under_Utank4_46 : 48|16@1+ (0.1,0) [0|6553.5] "V"  PC

BO_ 2417225327 S2P_Lmt11__47: 8 SBMU
 SG_ S2P_Lmt11_Over_DeltTcell1_47 : 0|8@1+ (1,-50) [-50|205] "℃"  PC
 SG_ S2P_Lmt11_Over_DeltTcell2_47 : 8|8@1+ (1,-50) [-50|205] "℃"  PC
 SG_ S2P_Lmt11_Over_DeltTcell3_47 : 16|8@1+ (1,-50) [-50|205] "℃"  PC
 SG_ S2P_Lmt11_Over_DDeltTcell_47 : 24|8@1+ (1,-50) [-50|205] "℃"  PC
 SG_ S2P_Lmt11_Over_Utank4_47 : 32|16@1+ (0.1,0) [0|6553.5] "V"  PC
 SG_ S2P_Lmt11_Under_Utank4_47 : 48|16@1+ (0.1,0) [0|6553.5] "V"  PC

BO_ 2417225328 S2P_Lmt11__48: 8 SBMU
 SG_ S2P_Lmt11_Over_DeltTcell1_48 : 0|8@1+ (1,-50) [-50|205] "℃"  PC
 SG_ S2P_Lmt11_Over_DeltTcell2_48 : 8|8@1+ (1,-50) [-50|205] "℃"  PC
 SG_ S2P_Lmt11_Over_DeltTcell3_48 : 16|8@1+ (1,-50) [-50|205] "℃"  PC
 SG_ S2P_Lmt11_Over_DDeltTcell_48 : 24|8@1+ (1,-50) [-50|205] "℃"  PC
 SG_ S2P_Lmt11_Over_Utank4_48 : 32|16@1+ (0.1,0) [0|6553.5] "V"  PC
 SG_ S2P_Lmt11_Under_Utank4_48 : 48|16@1+ (0.1,0) [0|6553.5] "V"  PC

BO_ 2417225329 S2P_Lmt11__49: 8 SBMU
 SG_ S2P_Lmt11_Over_DeltTcell1_49 : 0|8@1+ (1,-50) [-50|205] "℃"  PC
 SG_ S2P_Lmt11_Over_DeltTcell2_49 : 8|8@1+ (1,-50) [-50|205] "℃"  PC
 SG_ S2P_Lmt11_Over_DeltTcell3_49 : 16|8@1+ (1,-50) [-50|205] "℃"  PC
 SG_ S2P_Lmt11_Over_DDeltTcell_49 : 24|8@1+ (1,-50) [-50|205] "℃"  PC
 SG_ S2P_Lmt11_Over_Utank4_49 : 32|16@1+ (0.1,0) [0|6553.5] "V"  PC
 SG_ S2P_Lmt11_Under_Utank4_49 : 48|16@1+ (0.1,0) [0|6553.5] "V"  PC

BO_ 2417225330 S2P_Lmt11__50: 8 SBMU
 SG_ S2P_Lmt11_Over_DeltTcell1_50 : 0|8@1+ (1,-50) [-50|205] "℃"  PC
 SG_ S2P_Lmt11_Over_DeltTcell2_50 : 8|8@1+ (1,-50) [-50|205] "℃"  PC
 SG_ S2P_Lmt11_Over_DeltTcell3_50 : 16|8@1+ (1,-50) [-50|205] "℃"  PC
 SG_ S2P_Lmt11_Over_DDeltTcell_50 : 24|8@1+ (1,-50) [-50|205] "℃"  PC
 SG_ S2P_Lmt11_Over_Utank4_50 : 32|16@1+ (0.1,0) [0|6553.5] "V"  PC
 SG_ S2P_Lmt11_Under_Utank4_50 : 48|16@1+ (0.1,0) [0|6553.5] "V"  PC

BO_ 2417225331 S2P_Lmt11__51: 8 SBMU
 SG_ S2P_Lmt11_Over_DeltTcell1_51 : 0|8@1+ (1,-50) [-50|205] "℃"  PC
 SG_ S2P_Lmt11_Over_DeltTcell2_51 : 8|8@1+ (1,-50) [-50|205] "℃"  PC
 SG_ S2P_Lmt11_Over_DeltTcell3_51 : 16|8@1+ (1,-50) [-50|205] "℃"  PC
 SG_ S2P_Lmt11_Over_DDeltTcell_51 : 24|8@1+ (1,-50) [-50|205] "℃"  PC
 SG_ S2P_Lmt11_Over_Utank4_51 : 32|16@1+ (0.1,0) [0|6553.5] "V"  PC
 SG_ S2P_Lmt11_Under_Utank4_51 : 48|16@1+ (0.1,0) [0|6553.5] "V"  PC

BO_ 2417225332 S2P_Lmt11__52: 8 SBMU
 SG_ S2P_Lmt11_Over_DeltTcell1_52 : 0|8@1+ (1,-50) [-50|205] "℃"  PC
 SG_ S2P_Lmt11_Over_DeltTcell2_52 : 8|8@1+ (1,-50) [-50|205] "℃"  PC
 SG_ S2P_Lmt11_Over_DeltTcell3_52 : 16|8@1+ (1,-50) [-50|205] "℃"  PC
 SG_ S2P_Lmt11_Over_DDeltTcell_52 : 24|8@1+ (1,-50) [-50|205] "℃"  PC
 SG_ S2P_Lmt11_Over_Utank4_52 : 32|16@1+ (0.1,0) [0|6553.5] "V"  PC
 SG_ S2P_Lmt11_Under_Utank4_52 : 48|16@1+ (0.1,0) [0|6553.5] "V"  PC

BO_ 2417225333 S2P_Lmt11__53: 8 SBMU
 SG_ S2P_Lmt11_Over_DeltTcell1_53 : 0|8@1+ (1,-50) [-50|205] "℃"  PC
 SG_ S2P_Lmt11_Over_DeltTcell2_53 : 8|8@1+ (1,-50) [-50|205] "℃"  PC
 SG_ S2P_Lmt11_Over_DeltTcell3_53 : 16|8@1+ (1,-50) [-50|205] "℃"  PC
 SG_ S2P_Lmt11_Over_DDeltTcell_53 : 24|8@1+ (1,-50) [-50|205] "℃"  PC
 SG_ S2P_Lmt11_Over_Utank4_53 : 32|16@1+ (0.1,0) [0|6553.5] "V"  PC
 SG_ S2P_Lmt11_Under_Utank4_53 : 48|16@1+ (0.1,0) [0|6553.5] "V"  PC

BO_ 2417225334 S2P_Lmt11__54: 8 SBMU
 SG_ S2P_Lmt11_Over_DeltTcell1_54 : 0|8@1+ (1,-50) [-50|205] "℃"  PC
 SG_ S2P_Lmt11_Over_DeltTcell2_54 : 8|8@1+ (1,-50) [-50|205] "℃"  PC
 SG_ S2P_Lmt11_Over_DeltTcell3_54 : 16|8@1+ (1,-50) [-50|205] "℃"  PC
 SG_ S2P_Lmt11_Over_DDeltTcell_54 : 24|8@1+ (1,-50) [-50|205] "℃"  PC
 SG_ S2P_Lmt11_Over_Utank4_54 : 32|16@1+ (0.1,0) [0|6553.5] "V"  PC
 SG_ S2P_Lmt11_Under_Utank4_54 : 48|16@1+ (0.1,0) [0|6553.5] "V"  PC

BO_ 2417225335 S2P_Lmt11__55: 8 SBMU
 SG_ S2P_Lmt11_Over_DeltTcell1_55 : 0|8@1+ (1,-50) [-50|205] "℃"  PC
 SG_ S2P_Lmt11_Over_DeltTcell2_55 : 8|8@1+ (1,-50) [-50|205] "℃"  PC
 SG_ S2P_Lmt11_Over_DeltTcell3_55 : 16|8@1+ (1,-50) [-50|205] "℃"  PC
 SG_ S2P_Lmt11_Over_DDeltTcell_55 : 24|8@1+ (1,-50) [-50|205] "℃"  PC
 SG_ S2P_Lmt11_Over_Utank4_55 : 32|16@1+ (0.1,0) [0|6553.5] "V"  PC
 SG_ S2P_Lmt11_Under_Utank4_55 : 48|16@1+ (0.1,0) [0|6553.5] "V"  PC

BO_ 2417225336 S2P_Lmt11__56: 8 SBMU
 SG_ S2P_Lmt11_Over_DeltTcell1_56 : 0|8@1+ (1,-50) [-50|205] "℃"  PC
 SG_ S2P_Lmt11_Over_DeltTcell2_56 : 8|8@1+ (1,-50) [-50|205] "℃"  PC
 SG_ S2P_Lmt11_Over_DeltTcell3_56 : 16|8@1+ (1,-50) [-50|205] "℃"  PC
 SG_ S2P_Lmt11_Over_DDeltTcell_56 : 24|8@1+ (1,-50) [-50|205] "℃"  PC
 SG_ S2P_Lmt11_Over_Utank4_56 : 32|16@1+ (0.1,0) [0|6553.5] "V"  PC
 SG_ S2P_Lmt11_Under_Utank4_56 : 48|16@1+ (0.1,0) [0|6553.5] "V"  PC

BO_ 2417225337 S2P_Lmt11__57: 8 SBMU
 SG_ S2P_Lmt11_Over_DeltTcell1_57 : 0|8@1+ (1,-50) [-50|205] "℃"  PC
 SG_ S2P_Lmt11_Over_DeltTcell2_57 : 8|8@1+ (1,-50) [-50|205] "℃"  PC
 SG_ S2P_Lmt11_Over_DeltTcell3_57 : 16|8@1+ (1,-50) [-50|205] "℃"  PC
 SG_ S2P_Lmt11_Over_DDeltTcell_57 : 24|8@1+ (1,-50) [-50|205] "℃"  PC
 SG_ S2P_Lmt11_Over_Utank4_57 : 32|16@1+ (0.1,0) [0|6553.5] "V"  PC
 SG_ S2P_Lmt11_Under_Utank4_57 : 48|16@1+ (0.1,0) [0|6553.5] "V"  PC

BO_ 2417225338 S2P_Lmt11__58: 8 SBMU
 SG_ S2P_Lmt11_Over_DeltTcell1_58 : 0|8@1+ (1,-50) [-50|205] "℃"  PC
 SG_ S2P_Lmt11_Over_DeltTcell2_58 : 8|8@1+ (1,-50) [-50|205] "℃"  PC
 SG_ S2P_Lmt11_Over_DeltTcell3_58 : 16|8@1+ (1,-50) [-50|205] "℃"  PC
 SG_ S2P_Lmt11_Over_DDeltTcell_58 : 24|8@1+ (1,-50) [-50|205] "℃"  PC
 SG_ S2P_Lmt11_Over_Utank4_58 : 32|16@1+ (0.1,0) [0|6553.5] "V"  PC
 SG_ S2P_Lmt11_Under_Utank4_58 : 48|16@1+ (0.1,0) [0|6553.5] "V"  PC

BO_ 2417225339 S2P_Lmt11__59: 8 SBMU
 SG_ S2P_Lmt11_Over_DeltTcell1_59 : 0|8@1+ (1,-50) [-50|205] "℃"  PC
 SG_ S2P_Lmt11_Over_DeltTcell2_59 : 8|8@1+ (1,-50) [-50|205] "℃"  PC
 SG_ S2P_Lmt11_Over_DeltTcell3_59 : 16|8@1+ (1,-50) [-50|205] "℃"  PC
 SG_ S2P_Lmt11_Over_DDeltTcell_59 : 24|8@1+ (1,-50) [-50|205] "℃"  PC
 SG_ S2P_Lmt11_Over_Utank4_59 : 32|16@1+ (0.1,0) [0|6553.5] "V"  PC
 SG_ S2P_Lmt11_Under_Utank4_59 : 48|16@1+ (0.1,0) [0|6553.5] "V"  PC

BO_ 2417225340 S2P_Lmt11__60: 8 SBMU
 SG_ S2P_Lmt11_Over_DeltTcell1_60 : 0|8@1+ (1,-50) [-50|205] "℃"  PC
 SG_ S2P_Lmt11_Over_DeltTcell2_60 : 8|8@1+ (1,-50) [-50|205] "℃"  PC
 SG_ S2P_Lmt11_Over_DeltTcell3_60 : 16|8@1+ (1,-50) [-50|205] "℃"  PC
 SG_ S2P_Lmt11_Over_DDeltTcell_60 : 24|8@1+ (1,-50) [-50|205] "℃"  PC
 SG_ S2P_Lmt11_Over_Utank4_60 : 32|16@1+ (0.1,0) [0|6553.5] "V"  PC
 SG_ S2P_Lmt11_Under_Utank4_60 : 48|16@1+ (0.1,0) [0|6553.5] "V"  PC

BO_ 2417225341 S2P_Lmt11__61: 8 SBMU
 SG_ S2P_Lmt11_Over_DeltTcell1_61 : 0|8@1+ (1,-50) [-50|205] "℃"  PC
 SG_ S2P_Lmt11_Over_DeltTcell2_61 : 8|8@1+ (1,-50) [-50|205] "℃"  PC
 SG_ S2P_Lmt11_Over_DeltTcell3_61 : 16|8@1+ (1,-50) [-50|205] "℃"  PC
 SG_ S2P_Lmt11_Over_DDeltTcell_61 : 24|8@1+ (1,-50) [-50|205] "℃"  PC
 SG_ S2P_Lmt11_Over_Utank4_61 : 32|16@1+ (0.1,0) [0|6553.5] "V"  PC
 SG_ S2P_Lmt11_Under_Utank4_61 : 48|16@1+ (0.1,0) [0|6553.5] "V"  PC

BO_ 2417225342 S2P_Lmt11__62: 8 SBMU
 SG_ S2P_Lmt11_Over_DeltTcell1_62 : 0|8@1+ (1,-50) [-50|205] "℃"  PC
 SG_ S2P_Lmt11_Over_DeltTcell2_62 : 8|8@1+ (1,-50) [-50|205] "℃"  PC
 SG_ S2P_Lmt11_Over_DeltTcell3_62 : 16|8@1+ (1,-50) [-50|205] "℃"  PC
 SG_ S2P_Lmt11_Over_DDeltTcell_62 : 24|8@1+ (1,-50) [-50|205] "℃"  PC
 SG_ S2P_Lmt11_Over_Utank4_62 : 32|16@1+ (0.1,0) [0|6553.5] "V"  PC
 SG_ S2P_Lmt11_Under_Utank4_62 : 48|16@1+ (0.1,0) [0|6553.5] "V"  PC

BO_ 2417225343 S2P_Lmt11__63: 8 SBMU
 SG_ S2P_Lmt11_Over_DeltTcell1_63 : 0|8@1+ (1,-50) [-50|205] "℃"  PC
 SG_ S2P_Lmt11_Over_DeltTcell2_63 : 8|8@1+ (1,-50) [-50|205] "℃"  PC
 SG_ S2P_Lmt11_Over_DeltTcell3_63 : 16|8@1+ (1,-50) [-50|205] "℃"  PC
 SG_ S2P_Lmt11_Over_DDeltTcell_63 : 24|8@1+ (1,-50) [-50|205] "℃"  PC
 SG_ S2P_Lmt11_Over_Utank4_63 : 32|16@1+ (0.1,0) [0|6553.5] "V"  PC
 SG_ S2P_Lmt11_Under_Utank4_63 : 48|16@1+ (0.1,0) [0|6553.5] "V"  PC

BO_ 2417290817 S2P_Lmt12__01: 8 SBMU
 SG_ S2P_Lmt12_Over_Icharge1_01 : 0|16@1+ (0.01,0) [0|655.35] "A"  PC
 SG_ S2P_Lmt12_Over_Icharge2_01 : 16|16@1+ (0.01,0) [0|655.35] "A"  PC
 SG_ S2P_Lmt12_Over_Icharge3_01 : 32|16@1+ (0.01,0) [0|655.35] "A"  PC
 SG_ S2P_Lmt12_Over_Icharge4_01 : 48|16@1+ (0.01,0) [0|655.35] "A"  PC

BO_ 2417290818 S2P_Lmt12__02: 8 SBMU
 SG_ S2P_Lmt12_Over_Icharge1_02 : 0|16@1+ (0.01,0) [0|655.35] "A"  PC
 SG_ S2P_Lmt12_Over_Icharge2_02 : 16|16@1+ (0.01,0) [0|655.35] "A"  PC
 SG_ S2P_Lmt12_Over_Icharge3_02 : 32|16@1+ (0.01,0) [0|655.35] "A"  PC
 SG_ S2P_Lmt12_Over_Icharge4_02 : 48|16@1+ (0.01,0) [0|655.35] "A"  PC

BO_ 2417290819 S2P_Lmt12__03: 8 SBMU
 SG_ S2P_Lmt12_Over_Icharge1_03 : 0|16@1+ (0.01,0) [0|655.35] "A"  PC
 SG_ S2P_Lmt12_Over_Icharge2_03 : 16|16@1+ (0.01,0) [0|655.35] "A"  PC
 SG_ S2P_Lmt12_Over_Icharge3_03 : 32|16@1+ (0.01,0) [0|655.35] "A"  PC
 SG_ S2P_Lmt12_Over_Icharge4_03 : 48|16@1+ (0.01,0) [0|655.35] "A"  PC

BO_ 2417290820 S2P_Lmt12__04: 8 SBMU
 SG_ S2P_Lmt12_Over_Icharge1_04 : 0|16@1+ (0.01,0) [0|655.35] "A"  PC
 SG_ S2P_Lmt12_Over_Icharge2_04 : 16|16@1+ (0.01,0) [0|655.35] "A"  PC
 SG_ S2P_Lmt12_Over_Icharge3_04 : 32|16@1+ (0.01,0) [0|655.35] "A"  PC
 SG_ S2P_Lmt12_Over_Icharge4_04 : 48|16@1+ (0.01,0) [0|655.35] "A"  PC

BO_ 2417290821 S2P_Lmt12__05: 8 SBMU
 SG_ S2P_Lmt12_Over_Icharge1_05 : 0|16@1+ (0.01,0) [0|655.35] "A"  PC
 SG_ S2P_Lmt12_Over_Icharge2_05 : 16|16@1+ (0.01,0) [0|655.35] "A"  PC
 SG_ S2P_Lmt12_Over_Icharge3_05 : 32|16@1+ (0.01,0) [0|655.35] "A"  PC
 SG_ S2P_Lmt12_Over_Icharge4_05 : 48|16@1+ (0.01,0) [0|655.35] "A"  PC

BO_ 2417290822 S2P_Lmt12__06: 8 SBMU
 SG_ S2P_Lmt12_Over_Icharge1_06 : 0|16@1+ (0.01,0) [0|655.35] "A"  PC
 SG_ S2P_Lmt12_Over_Icharge2_06 : 16|16@1+ (0.01,0) [0|655.35] "A"  PC
 SG_ S2P_Lmt12_Over_Icharge3_06 : 32|16@1+ (0.01,0) [0|655.35] "A"  PC
 SG_ S2P_Lmt12_Over_Icharge4_06 : 48|16@1+ (0.01,0) [0|655.35] "A"  PC

BO_ 2417290823 S2P_Lmt12__07: 8 SBMU
 SG_ S2P_Lmt12_Over_Icharge1_07 : 0|16@1+ (0.01,0) [0|655.35] "A"  PC
 SG_ S2P_Lmt12_Over_Icharge2_07 : 16|16@1+ (0.01,0) [0|655.35] "A"  PC
 SG_ S2P_Lmt12_Over_Icharge3_07 : 32|16@1+ (0.01,0) [0|655.35] "A"  PC
 SG_ S2P_Lmt12_Over_Icharge4_07 : 48|16@1+ (0.01,0) [0|655.35] "A"  PC

BO_ 2417290824 S2P_Lmt12__08: 8 SBMU
 SG_ S2P_Lmt12_Over_Icharge1_08 : 0|16@1+ (0.01,0) [0|655.35] "A"  PC
 SG_ S2P_Lmt12_Over_Icharge2_08 : 16|16@1+ (0.01,0) [0|655.35] "A"  PC
 SG_ S2P_Lmt12_Over_Icharge3_08 : 32|16@1+ (0.01,0) [0|655.35] "A"  PC
 SG_ S2P_Lmt12_Over_Icharge4_08 : 48|16@1+ (0.01,0) [0|655.35] "A"  PC

BO_ 2417290825 S2P_Lmt12__09: 8 SBMU
 SG_ S2P_Lmt12_Over_Icharge1_09 : 0|16@1+ (0.01,0) [0|655.35] "A"  PC
 SG_ S2P_Lmt12_Over_Icharge2_09 : 16|16@1+ (0.01,0) [0|655.35] "A"  PC
 SG_ S2P_Lmt12_Over_Icharge3_09 : 32|16@1+ (0.01,0) [0|655.35] "A"  PC
 SG_ S2P_Lmt12_Over_Icharge4_09 : 48|16@1+ (0.01,0) [0|655.35] "A"  PC

BO_ 2417290826 S2P_Lmt12__10: 8 SBMU
 SG_ S2P_Lmt12_Over_Icharge1_10 : 0|16@1+ (0.01,0) [0|655.35] "A"  PC
 SG_ S2P_Lmt12_Over_Icharge2_10 : 16|16@1+ (0.01,0) [0|655.35] "A"  PC
 SG_ S2P_Lmt12_Over_Icharge3_10 : 32|16@1+ (0.01,0) [0|655.35] "A"  PC
 SG_ S2P_Lmt12_Over_Icharge4_10 : 48|16@1+ (0.01,0) [0|655.35] "A"  PC

BO_ 2417290827 S2P_Lmt12__11: 8 SBMU
 SG_ S2P_Lmt12_Over_Icharge1_11 : 0|16@1+ (0.01,0) [0|655.35] "A"  PC
 SG_ S2P_Lmt12_Over_Icharge2_11 : 16|16@1+ (0.01,0) [0|655.35] "A"  PC
 SG_ S2P_Lmt12_Over_Icharge3_11 : 32|16@1+ (0.01,0) [0|655.35] "A"  PC
 SG_ S2P_Lmt12_Over_Icharge4_11 : 48|16@1+ (0.01,0) [0|655.35] "A"  PC

BO_ 2417290828 S2P_Lmt12__12: 8 SBMU
 SG_ S2P_Lmt12_Over_Icharge1_12 : 0|16@1+ (0.01,0) [0|655.35] "A"  PC
 SG_ S2P_Lmt12_Over_Icharge2_12 : 16|16@1+ (0.01,0) [0|655.35] "A"  PC
 SG_ S2P_Lmt12_Over_Icharge3_12 : 32|16@1+ (0.01,0) [0|655.35] "A"  PC
 SG_ S2P_Lmt12_Over_Icharge4_12 : 48|16@1+ (0.01,0) [0|655.35] "A"  PC

BO_ 2417290829 S2P_Lmt12__13: 8 SBMU
 SG_ S2P_Lmt12_Over_Icharge1_13 : 0|16@1+ (0.01,0) [0|655.35] "A"  PC
 SG_ S2P_Lmt12_Over_Icharge2_13 : 16|16@1+ (0.01,0) [0|655.35] "A"  PC
 SG_ S2P_Lmt12_Over_Icharge3_13 : 32|16@1+ (0.01,0) [0|655.35] "A"  PC
 SG_ S2P_Lmt12_Over_Icharge4_13 : 48|16@1+ (0.01,0) [0|655.35] "A"  PC

BO_ 2417290830 S2P_Lmt12__14: 8 SBMU
 SG_ S2P_Lmt12_Over_Icharge1_14 : 0|16@1+ (0.01,0) [0|655.35] "A"  PC
 SG_ S2P_Lmt12_Over_Icharge2_14 : 16|16@1+ (0.01,0) [0|655.35] "A"  PC
 SG_ S2P_Lmt12_Over_Icharge3_14 : 32|16@1+ (0.01,0) [0|655.35] "A"  PC
 SG_ S2P_Lmt12_Over_Icharge4_14 : 48|16@1+ (0.01,0) [0|655.35] "A"  PC

BO_ 2417290831 S2P_Lmt12__15: 8 SBMU
 SG_ S2P_Lmt12_Over_Icharge1_15 : 0|16@1+ (0.01,0) [0|655.35] "A"  PC
 SG_ S2P_Lmt12_Over_Icharge2_15 : 16|16@1+ (0.01,0) [0|655.35] "A"  PC
 SG_ S2P_Lmt12_Over_Icharge3_15 : 32|16@1+ (0.01,0) [0|655.35] "A"  PC
 SG_ S2P_Lmt12_Over_Icharge4_15 : 48|16@1+ (0.01,0) [0|655.35] "A"  PC

BO_ 2417290832 S2P_Lmt12__16: 8 SBMU
 SG_ S2P_Lmt12_Over_Icharge1_16 : 0|16@1+ (0.01,0) [0|655.35] "A"  PC
 SG_ S2P_Lmt12_Over_Icharge2_16 : 16|16@1+ (0.01,0) [0|655.35] "A"  PC
 SG_ S2P_Lmt12_Over_Icharge3_16 : 32|16@1+ (0.01,0) [0|655.35] "A"  PC
 SG_ S2P_Lmt12_Over_Icharge4_16 : 48|16@1+ (0.01,0) [0|655.35] "A"  PC

BO_ 2417290833 S2P_Lmt12__17: 8 SBMU
 SG_ S2P_Lmt12_Over_Icharge1_17 : 0|16@1+ (0.01,0) [0|655.35] "A"  PC
 SG_ S2P_Lmt12_Over_Icharge2_17 : 16|16@1+ (0.01,0) [0|655.35] "A"  PC
 SG_ S2P_Lmt12_Over_Icharge3_17 : 32|16@1+ (0.01,0) [0|655.35] "A"  PC
 SG_ S2P_Lmt12_Over_Icharge4_17 : 48|16@1+ (0.01,0) [0|655.35] "A"  PC

BO_ 2417290834 S2P_Lmt12__18: 8 SBMU
 SG_ S2P_Lmt12_Over_Icharge1_18 : 0|16@1+ (0.01,0) [0|655.35] "A"  PC
 SG_ S2P_Lmt12_Over_Icharge2_18 : 16|16@1+ (0.01,0) [0|655.35] "A"  PC
 SG_ S2P_Lmt12_Over_Icharge3_18 : 32|16@1+ (0.01,0) [0|655.35] "A"  PC
 SG_ S2P_Lmt12_Over_Icharge4_18 : 48|16@1+ (0.01,0) [0|655.35] "A"  PC

BO_ 2417290835 S2P_Lmt12__19: 8 SBMU
 SG_ S2P_Lmt12_Over_Icharge1_19 : 0|16@1+ (0.01,0) [0|655.35] "A"  PC
 SG_ S2P_Lmt12_Over_Icharge2_19 : 16|16@1+ (0.01,0) [0|655.35] "A"  PC
 SG_ S2P_Lmt12_Over_Icharge3_19 : 32|16@1+ (0.01,0) [0|655.35] "A"  PC
 SG_ S2P_Lmt12_Over_Icharge4_19 : 48|16@1+ (0.01,0) [0|655.35] "A"  PC

BO_ 2417290836 S2P_Lmt12__20: 8 SBMU
 SG_ S2P_Lmt12_Over_Icharge1_20 : 0|16@1+ (0.01,0) [0|655.35] "A"  PC
 SG_ S2P_Lmt12_Over_Icharge2_20 : 16|16@1+ (0.01,0) [0|655.35] "A"  PC
 SG_ S2P_Lmt12_Over_Icharge3_20 : 32|16@1+ (0.01,0) [0|655.35] "A"  PC
 SG_ S2P_Lmt12_Over_Icharge4_20 : 48|16@1+ (0.01,0) [0|655.35] "A"  PC

BO_ 2417290837 S2P_Lmt12__21: 8 SBMU
 SG_ S2P_Lmt12_Over_Icharge1_21 : 0|16@1+ (0.01,0) [0|655.35] "A"  PC
 SG_ S2P_Lmt12_Over_Icharge2_21 : 16|16@1+ (0.01,0) [0|655.35] "A"  PC
 SG_ S2P_Lmt12_Over_Icharge3_21 : 32|16@1+ (0.01,0) [0|655.35] "A"  PC
 SG_ S2P_Lmt12_Over_Icharge4_21 : 48|16@1+ (0.01,0) [0|655.35] "A"  PC

BO_ 2417290838 S2P_Lmt12__22: 8 SBMU
 SG_ S2P_Lmt12_Over_Icharge1_22 : 0|16@1+ (0.01,0) [0|655.35] "A"  PC
 SG_ S2P_Lmt12_Over_Icharge2_22 : 16|16@1+ (0.01,0) [0|655.35] "A"  PC
 SG_ S2P_Lmt12_Over_Icharge3_22 : 32|16@1+ (0.01,0) [0|655.35] "A"  PC
 SG_ S2P_Lmt12_Over_Icharge4_22 : 48|16@1+ (0.01,0) [0|655.35] "A"  PC

BO_ 2417290839 S2P_Lmt12__23: 8 SBMU
 SG_ S2P_Lmt12_Over_Icharge1_23 : 0|16@1+ (0.01,0) [0|655.35] "A"  PC
 SG_ S2P_Lmt12_Over_Icharge2_23 : 16|16@1+ (0.01,0) [0|655.35] "A"  PC
 SG_ S2P_Lmt12_Over_Icharge3_23 : 32|16@1+ (0.01,0) [0|655.35] "A"  PC
 SG_ S2P_Lmt12_Over_Icharge4_23 : 48|16@1+ (0.01,0) [0|655.35] "A"  PC

BO_ 2417290840 S2P_Lmt12__24: 8 SBMU
 SG_ S2P_Lmt12_Over_Icharge1_24 : 0|16@1+ (0.01,0) [0|655.35] "A"  PC
 SG_ S2P_Lmt12_Over_Icharge2_24 : 16|16@1+ (0.01,0) [0|655.35] "A"  PC
 SG_ S2P_Lmt12_Over_Icharge3_24 : 32|16@1+ (0.01,0) [0|655.35] "A"  PC
 SG_ S2P_Lmt12_Over_Icharge4_24 : 48|16@1+ (0.01,0) [0|655.35] "A"  PC

BO_ 2417290841 S2P_Lmt12__25: 8 SBMU
 SG_ S2P_Lmt12_Over_Icharge1_25 : 0|16@1+ (0.01,0) [0|655.35] "A"  PC
 SG_ S2P_Lmt12_Over_Icharge2_25 : 16|16@1+ (0.01,0) [0|655.35] "A"  PC
 SG_ S2P_Lmt12_Over_Icharge3_25 : 32|16@1+ (0.01,0) [0|655.35] "A"  PC
 SG_ S2P_Lmt12_Over_Icharge4_25 : 48|16@1+ (0.01,0) [0|655.35] "A"  PC

BO_ 2417290842 S2P_Lmt12__26: 8 SBMU
 SG_ S2P_Lmt12_Over_Icharge1_26 : 0|16@1+ (0.01,0) [0|655.35] "A"  PC
 SG_ S2P_Lmt12_Over_Icharge2_26 : 16|16@1+ (0.01,0) [0|655.35] "A"  PC
 SG_ S2P_Lmt12_Over_Icharge3_26 : 32|16@1+ (0.01,0) [0|655.35] "A"  PC
 SG_ S2P_Lmt12_Over_Icharge4_26 : 48|16@1+ (0.01,0) [0|655.35] "A"  PC

BO_ 2417290843 S2P_Lmt12__27: 8 SBMU
 SG_ S2P_Lmt12_Over_Icharge1_27 : 0|16@1+ (0.01,0) [0|655.35] "A"  PC
 SG_ S2P_Lmt12_Over_Icharge2_27 : 16|16@1+ (0.01,0) [0|655.35] "A"  PC
 SG_ S2P_Lmt12_Over_Icharge3_27 : 32|16@1+ (0.01,0) [0|655.35] "A"  PC
 SG_ S2P_Lmt12_Over_Icharge4_27 : 48|16@1+ (0.01,0) [0|655.35] "A"  PC

BO_ 2417290844 S2P_Lmt12__28: 8 SBMU
 SG_ S2P_Lmt12_Over_Icharge1_28 : 0|16@1+ (0.01,0) [0|655.35] "A"  PC
 SG_ S2P_Lmt12_Over_Icharge2_28 : 16|16@1+ (0.01,0) [0|655.35] "A"  PC
 SG_ S2P_Lmt12_Over_Icharge3_28 : 32|16@1+ (0.01,0) [0|655.35] "A"  PC
 SG_ S2P_Lmt12_Over_Icharge4_28 : 48|16@1+ (0.01,0) [0|655.35] "A"  PC

BO_ 2417290845 S2P_Lmt12__29: 8 SBMU
 SG_ S2P_Lmt12_Over_Icharge1_29 : 0|16@1+ (0.01,0) [0|655.35] "A"  PC
 SG_ S2P_Lmt12_Over_Icharge2_29 : 16|16@1+ (0.01,0) [0|655.35] "A"  PC
 SG_ S2P_Lmt12_Over_Icharge3_29 : 32|16@1+ (0.01,0) [0|655.35] "A"  PC
 SG_ S2P_Lmt12_Over_Icharge4_29 : 48|16@1+ (0.01,0) [0|655.35] "A"  PC

BO_ 2417290846 S2P_Lmt12__30: 8 SBMU
 SG_ S2P_Lmt12_Over_Icharge1_30 : 0|16@1+ (0.01,0) [0|655.35] "A"  PC
 SG_ S2P_Lmt12_Over_Icharge2_30 : 16|16@1+ (0.01,0) [0|655.35] "A"  PC
 SG_ S2P_Lmt12_Over_Icharge3_30 : 32|16@1+ (0.01,0) [0|655.35] "A"  PC
 SG_ S2P_Lmt12_Over_Icharge4_30 : 48|16@1+ (0.01,0) [0|655.35] "A"  PC

BO_ 2417290847 S2P_Lmt12__31: 8 SBMU
 SG_ S2P_Lmt12_Over_Icharge1_31 : 0|16@1+ (0.01,0) [0|655.35] "A"  PC
 SG_ S2P_Lmt12_Over_Icharge2_31 : 16|16@1+ (0.01,0) [0|655.35] "A"  PC
 SG_ S2P_Lmt12_Over_Icharge3_31 : 32|16@1+ (0.01,0) [0|655.35] "A"  PC
 SG_ S2P_Lmt12_Over_Icharge4_31 : 48|16@1+ (0.01,0) [0|655.35] "A"  PC

BO_ 2417290848 S2P_Lmt12__32: 8 SBMU
 SG_ S2P_Lmt12_Over_Icharge1_32 : 0|16@1+ (0.01,0) [0|655.35] "A"  PC
 SG_ S2P_Lmt12_Over_Icharge2_32 : 16|16@1+ (0.01,0) [0|655.35] "A"  PC
 SG_ S2P_Lmt12_Over_Icharge3_32 : 32|16@1+ (0.01,0) [0|655.35] "A"  PC
 SG_ S2P_Lmt12_Over_Icharge4_32 : 48|16@1+ (0.01,0) [0|655.35] "A"  PC

BO_ 2417290849 S2P_Lmt12__33: 8 SBMU
 SG_ S2P_Lmt12_Over_Icharge1_33 : 0|16@1+ (0.01,0) [0|655.35] "A"  PC
 SG_ S2P_Lmt12_Over_Icharge2_33 : 16|16@1+ (0.01,0) [0|655.35] "A"  PC
 SG_ S2P_Lmt12_Over_Icharge3_33 : 32|16@1+ (0.01,0) [0|655.35] "A"  PC
 SG_ S2P_Lmt12_Over_Icharge4_33 : 48|16@1+ (0.01,0) [0|655.35] "A"  PC

BO_ 2417290850 S2P_Lmt12__34: 8 SBMU
 SG_ S2P_Lmt12_Over_Icharge1_34 : 0|16@1+ (0.01,0) [0|655.35] "A"  PC
 SG_ S2P_Lmt12_Over_Icharge2_34 : 16|16@1+ (0.01,0) [0|655.35] "A"  PC
 SG_ S2P_Lmt12_Over_Icharge3_34 : 32|16@1+ (0.01,0) [0|655.35] "A"  PC
 SG_ S2P_Lmt12_Over_Icharge4_34 : 48|16@1+ (0.01,0) [0|655.35] "A"  PC

BO_ 2417290851 S2P_Lmt12__35: 8 SBMU
 SG_ S2P_Lmt12_Over_Icharge1_35 : 0|16@1+ (0.01,0) [0|655.35] "A"  PC
 SG_ S2P_Lmt12_Over_Icharge2_35 : 16|16@1+ (0.01,0) [0|655.35] "A"  PC
 SG_ S2P_Lmt12_Over_Icharge3_35 : 32|16@1+ (0.01,0) [0|655.35] "A"  PC
 SG_ S2P_Lmt12_Over_Icharge4_35 : 48|16@1+ (0.01,0) [0|655.35] "A"  PC

BO_ 2417290852 S2P_Lmt12__36: 8 SBMU
 SG_ S2P_Lmt12_Over_Icharge1_36 : 0|16@1+ (0.01,0) [0|655.35] "A"  PC
 SG_ S2P_Lmt12_Over_Icharge2_36 : 16|16@1+ (0.01,0) [0|655.35] "A"  PC
 SG_ S2P_Lmt12_Over_Icharge3_36 : 32|16@1+ (0.01,0) [0|655.35] "A"  PC
 SG_ S2P_Lmt12_Over_Icharge4_36 : 48|16@1+ (0.01,0) [0|655.35] "A"  PC

BO_ 2417290853 S2P_Lmt12__37: 8 SBMU
 SG_ S2P_Lmt12_Over_Icharge1_37 : 0|16@1+ (0.01,0) [0|655.35] "A"  PC
 SG_ S2P_Lmt12_Over_Icharge2_37 : 16|16@1+ (0.01,0) [0|655.35] "A"  PC
 SG_ S2P_Lmt12_Over_Icharge3_37 : 32|16@1+ (0.01,0) [0|655.35] "A"  PC
 SG_ S2P_Lmt12_Over_Icharge4_37 : 48|16@1+ (0.01,0) [0|655.35] "A"  PC

BO_ 2417290854 S2P_Lmt12__38: 8 SBMU
 SG_ S2P_Lmt12_Over_Icharge1_38 : 0|16@1+ (0.01,0) [0|655.35] "A"  PC
 SG_ S2P_Lmt12_Over_Icharge2_38 : 16|16@1+ (0.01,0) [0|655.35] "A"  PC
 SG_ S2P_Lmt12_Over_Icharge3_38 : 32|16@1+ (0.01,0) [0|655.35] "A"  PC
 SG_ S2P_Lmt12_Over_Icharge4_38 : 48|16@1+ (0.01,0) [0|655.35] "A"  PC

BO_ 2417290855 S2P_Lmt12__39: 8 SBMU
 SG_ S2P_Lmt12_Over_Icharge1_39 : 0|16@1+ (0.01,0) [0|655.35] "A"  PC
 SG_ S2P_Lmt12_Over_Icharge2_39 : 16|16@1+ (0.01,0) [0|655.35] "A"  PC
 SG_ S2P_Lmt12_Over_Icharge3_39 : 32|16@1+ (0.01,0) [0|655.35] "A"  PC
 SG_ S2P_Lmt12_Over_Icharge4_39 : 48|16@1+ (0.01,0) [0|655.35] "A"  PC

BO_ 2417290856 S2P_Lmt12__40: 8 SBMU
 SG_ S2P_Lmt12_Over_Icharge1_40 : 0|16@1+ (0.01,0) [0|655.35] "A"  PC
 SG_ S2P_Lmt12_Over_Icharge2_40 : 16|16@1+ (0.01,0) [0|655.35] "A"  PC
 SG_ S2P_Lmt12_Over_Icharge3_40 : 32|16@1+ (0.01,0) [0|655.35] "A"  PC
 SG_ S2P_Lmt12_Over_Icharge4_40 : 48|16@1+ (0.01,0) [0|655.35] "A"  PC

BO_ 2417290857 S2P_Lmt12__41: 8 SBMU
 SG_ S2P_Lmt12_Over_Icharge1_41 : 0|16@1+ (0.01,0) [0|655.35] "A"  PC
 SG_ S2P_Lmt12_Over_Icharge2_41 : 16|16@1+ (0.01,0) [0|655.35] "A"  PC
 SG_ S2P_Lmt12_Over_Icharge3_41 : 32|16@1+ (0.01,0) [0|655.35] "A"  PC
 SG_ S2P_Lmt12_Over_Icharge4_41 : 48|16@1+ (0.01,0) [0|655.35] "A"  PC

BO_ 2417290858 S2P_Lmt12__42: 8 SBMU
 SG_ S2P_Lmt12_Over_Icharge1_42 : 0|16@1+ (0.01,0) [0|655.35] "A"  PC
 SG_ S2P_Lmt12_Over_Icharge2_42 : 16|16@1+ (0.01,0) [0|655.35] "A"  PC
 SG_ S2P_Lmt12_Over_Icharge3_42 : 32|16@1+ (0.01,0) [0|655.35] "A"  PC
 SG_ S2P_Lmt12_Over_Icharge4_42 : 48|16@1+ (0.01,0) [0|655.35] "A"  PC

BO_ 2417290859 S2P_Lmt12__43: 8 SBMU
 SG_ S2P_Lmt12_Over_Icharge1_43 : 0|16@1+ (0.01,0) [0|655.35] "A"  PC
 SG_ S2P_Lmt12_Over_Icharge2_43 : 16|16@1+ (0.01,0) [0|655.35] "A"  PC
 SG_ S2P_Lmt12_Over_Icharge3_43 : 32|16@1+ (0.01,0) [0|655.35] "A"  PC
 SG_ S2P_Lmt12_Over_Icharge4_43 : 48|16@1+ (0.01,0) [0|655.35] "A"  PC

BO_ 2417290860 S2P_Lmt12__44: 8 SBMU
 SG_ S2P_Lmt12_Over_Icharge1_44 : 0|16@1+ (0.01,0) [0|655.35] "A"  PC
 SG_ S2P_Lmt12_Over_Icharge2_44 : 16|16@1+ (0.01,0) [0|655.35] "A"  PC
 SG_ S2P_Lmt12_Over_Icharge3_44 : 32|16@1+ (0.01,0) [0|655.35] "A"  PC
 SG_ S2P_Lmt12_Over_Icharge4_44 : 48|16@1+ (0.01,0) [0|655.35] "A"  PC

BO_ 2417290861 S2P_Lmt12__45: 8 SBMU
 SG_ S2P_Lmt12_Over_Icharge1_45 : 0|16@1+ (0.01,0) [0|655.35] "A"  PC
 SG_ S2P_Lmt12_Over_Icharge2_45 : 16|16@1+ (0.01,0) [0|655.35] "A"  PC
 SG_ S2P_Lmt12_Over_Icharge3_45 : 32|16@1+ (0.01,0) [0|655.35] "A"  PC
 SG_ S2P_Lmt12_Over_Icharge4_45 : 48|16@1+ (0.01,0) [0|655.35] "A"  PC

BO_ 2417290862 S2P_Lmt12__46: 8 SBMU
 SG_ S2P_Lmt12_Over_Icharge1_46 : 0|16@1+ (0.01,0) [0|655.35] "A"  PC
 SG_ S2P_Lmt12_Over_Icharge2_46 : 16|16@1+ (0.01,0) [0|655.35] "A"  PC
 SG_ S2P_Lmt12_Over_Icharge3_46 : 32|16@1+ (0.01,0) [0|655.35] "A"  PC
 SG_ S2P_Lmt12_Over_Icharge4_46 : 48|16@1+ (0.01,0) [0|655.35] "A"  PC

BO_ 2417290863 S2P_Lmt12__47: 8 SBMU
 SG_ S2P_Lmt12_Over_Icharge1_47 : 0|16@1+ (0.01,0) [0|655.35] "A"  PC
 SG_ S2P_Lmt12_Over_Icharge2_47 : 16|16@1+ (0.01,0) [0|655.35] "A"  PC
 SG_ S2P_Lmt12_Over_Icharge3_47 : 32|16@1+ (0.01,0) [0|655.35] "A"  PC
 SG_ S2P_Lmt12_Over_Icharge4_47 : 48|16@1+ (0.01,0) [0|655.35] "A"  PC

BO_ 2417290864 S2P_Lmt12__48: 8 SBMU
 SG_ S2P_Lmt12_Over_Icharge1_48 : 0|16@1+ (0.01,0) [0|655.35] "A"  PC
 SG_ S2P_Lmt12_Over_Icharge2_48 : 16|16@1+ (0.01,0) [0|655.35] "A"  PC
 SG_ S2P_Lmt12_Over_Icharge3_48 : 32|16@1+ (0.01,0) [0|655.35] "A"  PC
 SG_ S2P_Lmt12_Over_Icharge4_48 : 48|16@1+ (0.01,0) [0|655.35] "A"  PC

BO_ 2417290865 S2P_Lmt12__49: 8 SBMU
 SG_ S2P_Lmt12_Over_Icharge1_49 : 0|16@1+ (0.01,0) [0|655.35] "A"  PC
 SG_ S2P_Lmt12_Over_Icharge2_49 : 16|16@1+ (0.01,0) [0|655.35] "A"  PC
 SG_ S2P_Lmt12_Over_Icharge3_49 : 32|16@1+ (0.01,0) [0|655.35] "A"  PC
 SG_ S2P_Lmt12_Over_Icharge4_49 : 48|16@1+ (0.01,0) [0|655.35] "A"  PC

BO_ 2417290866 S2P_Lmt12__50: 8 SBMU
 SG_ S2P_Lmt12_Over_Icharge1_50 : 0|16@1+ (0.01,0) [0|655.35] "A"  PC
 SG_ S2P_Lmt12_Over_Icharge2_50 : 16|16@1+ (0.01,0) [0|655.35] "A"  PC
 SG_ S2P_Lmt12_Over_Icharge3_50 : 32|16@1+ (0.01,0) [0|655.35] "A"  PC
 SG_ S2P_Lmt12_Over_Icharge4_50 : 48|16@1+ (0.01,0) [0|655.35] "A"  PC

BO_ 2417290867 S2P_Lmt12__51: 8 SBMU
 SG_ S2P_Lmt12_Over_Icharge1_51 : 0|16@1+ (0.01,0) [0|655.35] "A"  PC
 SG_ S2P_Lmt12_Over_Icharge2_51 : 16|16@1+ (0.01,0) [0|655.35] "A"  PC
 SG_ S2P_Lmt12_Over_Icharge3_51 : 32|16@1+ (0.01,0) [0|655.35] "A"  PC
 SG_ S2P_Lmt12_Over_Icharge4_51 : 48|16@1+ (0.01,0) [0|655.35] "A"  PC

BO_ 2417290868 S2P_Lmt12__52: 8 SBMU
 SG_ S2P_Lmt12_Over_Icharge1_52 : 0|16@1+ (0.01,0) [0|655.35] "A"  PC
 SG_ S2P_Lmt12_Over_Icharge2_52 : 16|16@1+ (0.01,0) [0|655.35] "A"  PC
 SG_ S2P_Lmt12_Over_Icharge3_52 : 32|16@1+ (0.01,0) [0|655.35] "A"  PC
 SG_ S2P_Lmt12_Over_Icharge4_52 : 48|16@1+ (0.01,0) [0|655.35] "A"  PC

BO_ 2417290869 S2P_Lmt12__53: 8 SBMU
 SG_ S2P_Lmt12_Over_Icharge1_53 : 0|16@1+ (0.01,0) [0|655.35] "A"  PC
 SG_ S2P_Lmt12_Over_Icharge2_53 : 16|16@1+ (0.01,0) [0|655.35] "A"  PC
 SG_ S2P_Lmt12_Over_Icharge3_53 : 32|16@1+ (0.01,0) [0|655.35] "A"  PC
 SG_ S2P_Lmt12_Over_Icharge4_53 : 48|16@1+ (0.01,0) [0|655.35] "A"  PC

BO_ 2417290870 S2P_Lmt12__54: 8 SBMU
 SG_ S2P_Lmt12_Over_Icharge1_54 : 0|16@1+ (0.01,0) [0|655.35] "A"  PC
 SG_ S2P_Lmt12_Over_Icharge2_54 : 16|16@1+ (0.01,0) [0|655.35] "A"  PC
 SG_ S2P_Lmt12_Over_Icharge3_54 : 32|16@1+ (0.01,0) [0|655.35] "A"  PC
 SG_ S2P_Lmt12_Over_Icharge4_54 : 48|16@1+ (0.01,0) [0|655.35] "A"  PC

BO_ 2417290871 S2P_Lmt12__55: 8 SBMU
 SG_ S2P_Lmt12_Over_Icharge1_55 : 0|16@1+ (0.01,0) [0|655.35] "A"  PC
 SG_ S2P_Lmt12_Over_Icharge2_55 : 16|16@1+ (0.01,0) [0|655.35] "A"  PC
 SG_ S2P_Lmt12_Over_Icharge3_55 : 32|16@1+ (0.01,0) [0|655.35] "A"  PC
 SG_ S2P_Lmt12_Over_Icharge4_55 : 48|16@1+ (0.01,0) [0|655.35] "A"  PC

BO_ 2417290872 S2P_Lmt12__56: 8 SBMU
 SG_ S2P_Lmt12_Over_Icharge1_56 : 0|16@1+ (0.01,0) [0|655.35] "A"  PC
 SG_ S2P_Lmt12_Over_Icharge2_56 : 16|16@1+ (0.01,0) [0|655.35] "A"  PC
 SG_ S2P_Lmt12_Over_Icharge3_56 : 32|16@1+ (0.01,0) [0|655.35] "A"  PC
 SG_ S2P_Lmt12_Over_Icharge4_56 : 48|16@1+ (0.01,0) [0|655.35] "A"  PC

BO_ 2417290873 S2P_Lmt12__57: 8 SBMU
 SG_ S2P_Lmt12_Over_Icharge1_57 : 0|16@1+ (0.01,0) [0|655.35] "A"  PC
 SG_ S2P_Lmt12_Over_Icharge2_57 : 16|16@1+ (0.01,0) [0|655.35] "A"  PC
 SG_ S2P_Lmt12_Over_Icharge3_57 : 32|16@1+ (0.01,0) [0|655.35] "A"  PC
 SG_ S2P_Lmt12_Over_Icharge4_57 : 48|16@1+ (0.01,0) [0|655.35] "A"  PC

BO_ 2417290874 S2P_Lmt12__58: 8 SBMU
 SG_ S2P_Lmt12_Over_Icharge1_58 : 0|16@1+ (0.01,0) [0|655.35] "A"  PC
 SG_ S2P_Lmt12_Over_Icharge2_58 : 16|16@1+ (0.01,0) [0|655.35] "A"  PC
 SG_ S2P_Lmt12_Over_Icharge3_58 : 32|16@1+ (0.01,0) [0|655.35] "A"  PC
 SG_ S2P_Lmt12_Over_Icharge4_58 : 48|16@1+ (0.01,0) [0|655.35] "A"  PC

BO_ 2417290875 S2P_Lmt12__59: 8 SBMU
 SG_ S2P_Lmt12_Over_Icharge1_59 : 0|16@1+ (0.01,0) [0|655.35] "A"  PC
 SG_ S2P_Lmt12_Over_Icharge2_59 : 16|16@1+ (0.01,0) [0|655.35] "A"  PC
 SG_ S2P_Lmt12_Over_Icharge3_59 : 32|16@1+ (0.01,0) [0|655.35] "A"  PC
 SG_ S2P_Lmt12_Over_Icharge4_59 : 48|16@1+ (0.01,0) [0|655.35] "A"  PC

BO_ 2417290876 S2P_Lmt12__60: 8 SBMU
 SG_ S2P_Lmt12_Over_Icharge1_60 : 0|16@1+ (0.01,0) [0|655.35] "A"  PC
 SG_ S2P_Lmt12_Over_Icharge2_60 : 16|16@1+ (0.01,0) [0|655.35] "A"  PC
 SG_ S2P_Lmt12_Over_Icharge3_60 : 32|16@1+ (0.01,0) [0|655.35] "A"  PC
 SG_ S2P_Lmt12_Over_Icharge4_60 : 48|16@1+ (0.01,0) [0|655.35] "A"  PC

BO_ 2417290877 S2P_Lmt12__61: 8 SBMU
 SG_ S2P_Lmt12_Over_Icharge1_61 : 0|16@1+ (0.01,0) [0|655.35] "A"  PC
 SG_ S2P_Lmt12_Over_Icharge2_61 : 16|16@1+ (0.01,0) [0|655.35] "A"  PC
 SG_ S2P_Lmt12_Over_Icharge3_61 : 32|16@1+ (0.01,0) [0|655.35] "A"  PC
 SG_ S2P_Lmt12_Over_Icharge4_61 : 48|16@1+ (0.01,0) [0|655.35] "A"  PC

BO_ 2417290878 S2P_Lmt12__62: 8 SBMU
 SG_ S2P_Lmt12_Over_Icharge1_62 : 0|16@1+ (0.01,0) [0|655.35] "A"  PC
 SG_ S2P_Lmt12_Over_Icharge2_62 : 16|16@1+ (0.01,0) [0|655.35] "A"  PC
 SG_ S2P_Lmt12_Over_Icharge3_62 : 32|16@1+ (0.01,0) [0|655.35] "A"  PC
 SG_ S2P_Lmt12_Over_Icharge4_62 : 48|16@1+ (0.01,0) [0|655.35] "A"  PC

BO_ 2417290879 S2P_Lmt12__63: 8 SBMU
 SG_ S2P_Lmt12_Over_Icharge1_63 : 0|16@1+ (0.01,0) [0|655.35] "A"  PC
 SG_ S2P_Lmt12_Over_Icharge2_63 : 16|16@1+ (0.01,0) [0|655.35] "A"  PC
 SG_ S2P_Lmt12_Over_Icharge3_63 : 32|16@1+ (0.01,0) [0|655.35] "A"  PC
 SG_ S2P_Lmt12_Over_Icharge4_63 : 48|16@1+ (0.01,0) [0|655.35] "A"  PC

BO_ 2417356353 S2P_Lmt13__01: 8 SBMU
 SG_ S2P_Lmt13_Over_SOC1_01 : 0|16@1+ (0.1,0) [0|6553.5] "%"  PC
 SG_ S2P_Lmt13_Over_SOC2_01 : 16|16@1+ (0.1,0) [0|6553.5] "%"  PC
 SG_ S2P_Lmt13_Over_SOC3_01 : 32|16@1+ (0.1,0) [0|6553.5] "%"  PC
 SG_ S2P_Lmt13_Over_DSOC_01 : 48|16@1+ (0.1,0) [0|6553.5] "%"  PC

BO_ 2417356354 S2P_Lmt13__02: 8 SBMU
 SG_ S2P_Lmt13_Over_SOC1_02 : 0|16@1+ (0.1,0) [0|6553.5] "%"  PC
 SG_ S2P_Lmt13_Over_SOC2_02 : 16|16@1+ (0.1,0) [0|6553.5] "%"  PC
 SG_ S2P_Lmt13_Over_SOC3_02 : 32|16@1+ (0.1,0) [0|6553.5] "%"  PC
 SG_ S2P_Lmt13_Over_DSOC_02 : 48|16@1+ (0.1,0) [0|6553.5] "%"  PC

BO_ 2417356355 S2P_Lmt13__03: 8 SBMU
 SG_ S2P_Lmt13_Over_SOC1_03 : 0|16@1+ (0.1,0) [0|6553.5] "%"  PC
 SG_ S2P_Lmt13_Over_SOC2_03 : 16|16@1+ (0.1,0) [0|6553.5] "%"  PC
 SG_ S2P_Lmt13_Over_SOC3_03 : 32|16@1+ (0.1,0) [0|6553.5] "%"  PC
 SG_ S2P_Lmt13_Over_DSOC_03 : 48|16@1+ (0.1,0) [0|6553.5] "%"  PC

BO_ 2417356356 S2P_Lmt13__04: 8 SBMU
 SG_ S2P_Lmt13_Over_SOC1_04 : 0|16@1+ (0.1,0) [0|6553.5] "%"  PC
 SG_ S2P_Lmt13_Over_SOC2_04 : 16|16@1+ (0.1,0) [0|6553.5] "%"  PC
 SG_ S2P_Lmt13_Over_SOC3_04 : 32|16@1+ (0.1,0) [0|6553.5] "%"  PC
 SG_ S2P_Lmt13_Over_DSOC_04 : 48|16@1+ (0.1,0) [0|6553.5] "%"  PC

BO_ 2417356357 S2P_Lmt13__05: 8 SBMU
 SG_ S2P_Lmt13_Over_SOC1_05 : 0|16@1+ (0.1,0) [0|6553.5] "%"  PC
 SG_ S2P_Lmt13_Over_SOC2_05 : 16|16@1+ (0.1,0) [0|6553.5] "%"  PC
 SG_ S2P_Lmt13_Over_SOC3_05 : 32|16@1+ (0.1,0) [0|6553.5] "%"  PC
 SG_ S2P_Lmt13_Over_DSOC_05 : 48|16@1+ (0.1,0) [0|6553.5] "%"  PC

BO_ 2417356358 S2P_Lmt13__06: 8 SBMU
 SG_ S2P_Lmt13_Over_SOC1_06 : 0|16@1+ (0.1,0) [0|6553.5] "%"  PC
 SG_ S2P_Lmt13_Over_SOC2_06 : 16|16@1+ (0.1,0) [0|6553.5] "%"  PC
 SG_ S2P_Lmt13_Over_SOC3_06 : 32|16@1+ (0.1,0) [0|6553.5] "%"  PC
 SG_ S2P_Lmt13_Over_DSOC_06 : 48|16@1+ (0.1,0) [0|6553.5] "%"  PC

BO_ 2417356359 S2P_Lmt13__07: 8 SBMU
 SG_ S2P_Lmt13_Over_SOC1_07 : 0|16@1+ (0.1,0) [0|6553.5] "%"  PC
 SG_ S2P_Lmt13_Over_SOC2_07 : 16|16@1+ (0.1,0) [0|6553.5] "%"  PC
 SG_ S2P_Lmt13_Over_SOC3_07 : 32|16@1+ (0.1,0) [0|6553.5] "%"  PC
 SG_ S2P_Lmt13_Over_DSOC_07 : 48|16@1+ (0.1,0) [0|6553.5] "%"  PC

BO_ 2417356360 S2P_Lmt13__08: 8 SBMU
 SG_ S2P_Lmt13_Over_SOC1_08 : 0|16@1+ (0.1,0) [0|6553.5] "%"  PC
 SG_ S2P_Lmt13_Over_SOC2_08 : 16|16@1+ (0.1,0) [0|6553.5] "%"  PC
 SG_ S2P_Lmt13_Over_SOC3_08 : 32|16@1+ (0.1,0) [0|6553.5] "%"  PC
 SG_ S2P_Lmt13_Over_DSOC_08 : 48|16@1+ (0.1,0) [0|6553.5] "%"  PC

BO_ 2417356361 S2P_Lmt13__09: 8 SBMU
 SG_ S2P_Lmt13_Over_SOC1_09 : 0|16@1+ (0.1,0) [0|6553.5] "%"  PC
 SG_ S2P_Lmt13_Over_SOC2_09 : 16|16@1+ (0.1,0) [0|6553.5] "%"  PC
 SG_ S2P_Lmt13_Over_SOC3_09 : 32|16@1+ (0.1,0) [0|6553.5] "%"  PC
 SG_ S2P_Lmt13_Over_DSOC_09 : 48|16@1+ (0.1,0) [0|6553.5] "%"  PC

BO_ 2417356362 S2P_Lmt13__10: 8 SBMU
 SG_ S2P_Lmt13_Over_SOC1_10 : 0|16@1+ (0.1,0) [0|6553.5] "%"  PC
 SG_ S2P_Lmt13_Over_SOC2_10 : 16|16@1+ (0.1,0) [0|6553.5] "%"  PC
 SG_ S2P_Lmt13_Over_SOC3_10 : 32|16@1+ (0.1,0) [0|6553.5] "%"  PC
 SG_ S2P_Lmt13_Over_DSOC_10 : 48|16@1+ (0.1,0) [0|6553.5] "%"  PC

BO_ 2417356363 S2P_Lmt13__11: 8 SBMU
 SG_ S2P_Lmt13_Over_SOC1_11 : 0|16@1+ (0.1,0) [0|6553.5] "%"  PC
 SG_ S2P_Lmt13_Over_SOC2_11 : 16|16@1+ (0.1,0) [0|6553.5] "%"  PC
 SG_ S2P_Lmt13_Over_SOC3_11 : 32|16@1+ (0.1,0) [0|6553.5] "%"  PC
 SG_ S2P_Lmt13_Over_DSOC_11 : 48|16@1+ (0.1,0) [0|6553.5] "%"  PC

BO_ 2417356364 S2P_Lmt13__12: 8 SBMU
 SG_ S2P_Lmt13_Over_SOC1_12 : 0|16@1+ (0.1,0) [0|6553.5] "%"  PC
 SG_ S2P_Lmt13_Over_SOC2_12 : 16|16@1+ (0.1,0) [0|6553.5] "%"  PC
 SG_ S2P_Lmt13_Over_SOC3_12 : 32|16@1+ (0.1,0) [0|6553.5] "%"  PC
 SG_ S2P_Lmt13_Over_DSOC_12 : 48|16@1+ (0.1,0) [0|6553.5] "%"  PC

BO_ 2417356365 S2P_Lmt13__13: 8 SBMU
 SG_ S2P_Lmt13_Over_SOC1_13 : 0|16@1+ (0.1,0) [0|6553.5] "%"  PC
 SG_ S2P_Lmt13_Over_SOC2_13 : 16|16@1+ (0.1,0) [0|6553.5] "%"  PC
 SG_ S2P_Lmt13_Over_SOC3_13 : 32|16@1+ (0.1,0) [0|6553.5] "%"  PC
 SG_ S2P_Lmt13_Over_DSOC_13 : 48|16@1+ (0.1,0) [0|6553.5] "%"  PC

BO_ 2417356366 S2P_Lmt13__14: 8 SBMU
 SG_ S2P_Lmt13_Over_SOC1_14 : 0|16@1+ (0.1,0) [0|6553.5] "%"  PC
 SG_ S2P_Lmt13_Over_SOC2_14 : 16|16@1+ (0.1,0) [0|6553.5] "%"  PC
 SG_ S2P_Lmt13_Over_SOC3_14 : 32|16@1+ (0.1,0) [0|6553.5] "%"  PC
 SG_ S2P_Lmt13_Over_DSOC_14 : 48|16@1+ (0.1,0) [0|6553.5] "%"  PC

BO_ 2417356367 S2P_Lmt13__15: 8 SBMU
 SG_ S2P_Lmt13_Over_SOC1_15 : 0|16@1+ (0.1,0) [0|6553.5] "%"  PC
 SG_ S2P_Lmt13_Over_SOC2_15 : 16|16@1+ (0.1,0) [0|6553.5] "%"  PC
 SG_ S2P_Lmt13_Over_SOC3_15 : 32|16@1+ (0.1,0) [0|6553.5] "%"  PC
 SG_ S2P_Lmt13_Over_DSOC_15 : 48|16@1+ (0.1,0) [0|6553.5] "%"  PC

BO_ 2417356368 S2P_Lmt13__16: 8 SBMU
 SG_ S2P_Lmt13_Over_SOC1_16 : 0|16@1+ (0.1,0) [0|6553.5] "%"  PC
 SG_ S2P_Lmt13_Over_SOC2_16 : 16|16@1+ (0.1,0) [0|6553.5] "%"  PC
 SG_ S2P_Lmt13_Over_SOC3_16 : 32|16@1+ (0.1,0) [0|6553.5] "%"  PC
 SG_ S2P_Lmt13_Over_DSOC_16 : 48|16@1+ (0.1,0) [0|6553.5] "%"  PC

BO_ 2417356369 S2P_Lmt13__17: 8 SBMU
 SG_ S2P_Lmt13_Over_SOC1_17 : 0|16@1+ (0.1,0) [0|6553.5] "%"  PC
 SG_ S2P_Lmt13_Over_SOC2_17 : 16|16@1+ (0.1,0) [0|6553.5] "%"  PC
 SG_ S2P_Lmt13_Over_SOC3_17 : 32|16@1+ (0.1,0) [0|6553.5] "%"  PC
 SG_ S2P_Lmt13_Over_DSOC_17 : 48|16@1+ (0.1,0) [0|6553.5] "%"  PC

BO_ 2417356370 S2P_Lmt13__18: 8 SBMU
 SG_ S2P_Lmt13_Over_SOC1_18 : 0|16@1+ (0.1,0) [0|6553.5] "%"  PC
 SG_ S2P_Lmt13_Over_SOC2_18 : 16|16@1+ (0.1,0) [0|6553.5] "%"  PC
 SG_ S2P_Lmt13_Over_SOC3_18 : 32|16@1+ (0.1,0) [0|6553.5] "%"  PC
 SG_ S2P_Lmt13_Over_DSOC_18 : 48|16@1+ (0.1,0) [0|6553.5] "%"  PC

BO_ 2417356371 S2P_Lmt13__19: 8 SBMU
 SG_ S2P_Lmt13_Over_SOC1_19 : 0|16@1+ (0.1,0) [0|6553.5] "%"  PC
 SG_ S2P_Lmt13_Over_SOC2_19 : 16|16@1+ (0.1,0) [0|6553.5] "%"  PC
 SG_ S2P_Lmt13_Over_SOC3_19 : 32|16@1+ (0.1,0) [0|6553.5] "%"  PC
 SG_ S2P_Lmt13_Over_DSOC_19 : 48|16@1+ (0.1,0) [0|6553.5] "%"  PC

BO_ 2417356372 S2P_Lmt13__20: 8 SBMU
 SG_ S2P_Lmt13_Over_SOC1_20 : 0|16@1+ (0.1,0) [0|6553.5] "%"  PC
 SG_ S2P_Lmt13_Over_SOC2_20 : 16|16@1+ (0.1,0) [0|6553.5] "%"  PC
 SG_ S2P_Lmt13_Over_SOC3_20 : 32|16@1+ (0.1,0) [0|6553.5] "%"  PC
 SG_ S2P_Lmt13_Over_DSOC_20 : 48|16@1+ (0.1,0) [0|6553.5] "%"  PC

BO_ 2417356373 S2P_Lmt13__21: 8 SBMU
 SG_ S2P_Lmt13_Over_SOC1_21 : 0|16@1+ (0.1,0) [0|6553.5] "%"  PC
 SG_ S2P_Lmt13_Over_SOC2_21 : 16|16@1+ (0.1,0) [0|6553.5] "%"  PC
 SG_ S2P_Lmt13_Over_SOC3_21 : 32|16@1+ (0.1,0) [0|6553.5] "%"  PC
 SG_ S2P_Lmt13_Over_DSOC_21 : 48|16@1+ (0.1,0) [0|6553.5] "%"  PC

BO_ 2417356374 S2P_Lmt13__22: 8 SBMU
 SG_ S2P_Lmt13_Over_SOC1_22 : 0|16@1+ (0.1,0) [0|6553.5] "%"  PC
 SG_ S2P_Lmt13_Over_SOC2_22 : 16|16@1+ (0.1,0) [0|6553.5] "%"  PC
 SG_ S2P_Lmt13_Over_SOC3_22 : 32|16@1+ (0.1,0) [0|6553.5] "%"  PC
 SG_ S2P_Lmt13_Over_DSOC_22 : 48|16@1+ (0.1,0) [0|6553.5] "%"  PC

BO_ 2417356375 S2P_Lmt13__23: 8 SBMU
 SG_ S2P_Lmt13_Over_SOC1_23 : 0|16@1+ (0.1,0) [0|6553.5] "%"  PC
 SG_ S2P_Lmt13_Over_SOC2_23 : 16|16@1+ (0.1,0) [0|6553.5] "%"  PC
 SG_ S2P_Lmt13_Over_SOC3_23 : 32|16@1+ (0.1,0) [0|6553.5] "%"  PC
 SG_ S2P_Lmt13_Over_DSOC_23 : 48|16@1+ (0.1,0) [0|6553.5] "%"  PC

BO_ 2417356376 S2P_Lmt13__24: 8 SBMU
 SG_ S2P_Lmt13_Over_SOC1_24 : 0|16@1+ (0.1,0) [0|6553.5] "%"  PC
 SG_ S2P_Lmt13_Over_SOC2_24 : 16|16@1+ (0.1,0) [0|6553.5] "%"  PC
 SG_ S2P_Lmt13_Over_SOC3_24 : 32|16@1+ (0.1,0) [0|6553.5] "%"  PC
 SG_ S2P_Lmt13_Over_DSOC_24 : 48|16@1+ (0.1,0) [0|6553.5] "%"  PC

BO_ 2417356377 S2P_Lmt13__25: 8 SBMU
 SG_ S2P_Lmt13_Over_SOC1_25 : 0|16@1+ (0.1,0) [0|6553.5] "%"  PC
 SG_ S2P_Lmt13_Over_SOC2_25 : 16|16@1+ (0.1,0) [0|6553.5] "%"  PC
 SG_ S2P_Lmt13_Over_SOC3_25 : 32|16@1+ (0.1,0) [0|6553.5] "%"  PC
 SG_ S2P_Lmt13_Over_DSOC_25 : 48|16@1+ (0.1,0) [0|6553.5] "%"  PC

BO_ 2417356378 S2P_Lmt13__26: 8 SBMU
 SG_ S2P_Lmt13_Over_SOC1_26 : 0|16@1+ (0.1,0) [0|6553.5] "%"  PC
 SG_ S2P_Lmt13_Over_SOC2_26 : 16|16@1+ (0.1,0) [0|6553.5] "%"  PC
 SG_ S2P_Lmt13_Over_SOC3_26 : 32|16@1+ (0.1,0) [0|6553.5] "%"  PC
 SG_ S2P_Lmt13_Over_DSOC_26 : 48|16@1+ (0.1,0) [0|6553.5] "%"  PC

BO_ 2417356379 S2P_Lmt13__27: 8 SBMU
 SG_ S2P_Lmt13_Over_SOC1_27 : 0|16@1+ (0.1,0) [0|6553.5] "%"  PC
 SG_ S2P_Lmt13_Over_SOC2_27 : 16|16@1+ (0.1,0) [0|6553.5] "%"  PC
 SG_ S2P_Lmt13_Over_SOC3_27 : 32|16@1+ (0.1,0) [0|6553.5] "%"  PC
 SG_ S2P_Lmt13_Over_DSOC_27 : 48|16@1+ (0.1,0) [0|6553.5] "%"  PC

BO_ 2417356380 S2P_Lmt13__28: 8 SBMU
 SG_ S2P_Lmt13_Over_SOC1_28 : 0|16@1+ (0.1,0) [0|6553.5] "%"  PC
 SG_ S2P_Lmt13_Over_SOC2_28 : 16|16@1+ (0.1,0) [0|6553.5] "%"  PC
 SG_ S2P_Lmt13_Over_SOC3_28 : 32|16@1+ (0.1,0) [0|6553.5] "%"  PC
 SG_ S2P_Lmt13_Over_DSOC_28 : 48|16@1+ (0.1,0) [0|6553.5] "%"  PC

BO_ 2417356381 S2P_Lmt13__29: 8 SBMU
 SG_ S2P_Lmt13_Over_SOC1_29 : 0|16@1+ (0.1,0) [0|6553.5] "%"  PC
 SG_ S2P_Lmt13_Over_SOC2_29 : 16|16@1+ (0.1,0) [0|6553.5] "%"  PC
 SG_ S2P_Lmt13_Over_SOC3_29 : 32|16@1+ (0.1,0) [0|6553.5] "%"  PC
 SG_ S2P_Lmt13_Over_DSOC_29 : 48|16@1+ (0.1,0) [0|6553.5] "%"  PC

BO_ 2417356382 S2P_Lmt13__30: 8 SBMU
 SG_ S2P_Lmt13_Over_SOC1_30 : 0|16@1+ (0.1,0) [0|6553.5] "%"  PC
 SG_ S2P_Lmt13_Over_SOC2_30 : 16|16@1+ (0.1,0) [0|6553.5] "%"  PC
 SG_ S2P_Lmt13_Over_SOC3_30 : 32|16@1+ (0.1,0) [0|6553.5] "%"  PC
 SG_ S2P_Lmt13_Over_DSOC_30 : 48|16@1+ (0.1,0) [0|6553.5] "%"  PC

BO_ 2417356383 S2P_Lmt13__31: 8 SBMU
 SG_ S2P_Lmt13_Over_SOC1_31 : 0|16@1+ (0.1,0) [0|6553.5] "%"  PC
 SG_ S2P_Lmt13_Over_SOC2_31 : 16|16@1+ (0.1,0) [0|6553.5] "%"  PC
 SG_ S2P_Lmt13_Over_SOC3_31 : 32|16@1+ (0.1,0) [0|6553.5] "%"  PC
 SG_ S2P_Lmt13_Over_DSOC_31 : 48|16@1+ (0.1,0) [0|6553.5] "%"  PC

BO_ 2417356384 S2P_Lmt13__32: 8 SBMU
 SG_ S2P_Lmt13_Over_SOC1_32 : 0|16@1+ (0.1,0) [0|6553.5] "%"  PC
 SG_ S2P_Lmt13_Over_SOC2_32 : 16|16@1+ (0.1,0) [0|6553.5] "%"  PC
 SG_ S2P_Lmt13_Over_SOC3_32 : 32|16@1+ (0.1,0) [0|6553.5] "%"  PC
 SG_ S2P_Lmt13_Over_DSOC_32 : 48|16@1+ (0.1,0) [0|6553.5] "%"  PC

BO_ 2417356385 S2P_Lmt13__33: 8 SBMU
 SG_ S2P_Lmt13_Over_SOC1_33 : 0|16@1+ (0.1,0) [0|6553.5] "%"  PC
 SG_ S2P_Lmt13_Over_SOC2_33 : 16|16@1+ (0.1,0) [0|6553.5] "%"  PC
 SG_ S2P_Lmt13_Over_SOC3_33 : 32|16@1+ (0.1,0) [0|6553.5] "%"  PC
 SG_ S2P_Lmt13_Over_DSOC_33 : 48|16@1+ (0.1,0) [0|6553.5] "%"  PC

BO_ 2417356386 S2P_Lmt13__34: 8 SBMU
 SG_ S2P_Lmt13_Over_SOC1_34 : 0|16@1+ (0.1,0) [0|6553.5] "%"  PC
 SG_ S2P_Lmt13_Over_SOC2_34 : 16|16@1+ (0.1,0) [0|6553.5] "%"  PC
 SG_ S2P_Lmt13_Over_SOC3_34 : 32|16@1+ (0.1,0) [0|6553.5] "%"  PC
 SG_ S2P_Lmt13_Over_DSOC_34 : 48|16@1+ (0.1,0) [0|6553.5] "%"  PC

BO_ 2417356387 S2P_Lmt13__35: 8 SBMU
 SG_ S2P_Lmt13_Over_SOC1_35 : 0|16@1+ (0.1,0) [0|6553.5] "%"  PC
 SG_ S2P_Lmt13_Over_SOC2_35 : 16|16@1+ (0.1,0) [0|6553.5] "%"  PC
 SG_ S2P_Lmt13_Over_SOC3_35 : 32|16@1+ (0.1,0) [0|6553.5] "%"  PC
 SG_ S2P_Lmt13_Over_DSOC_35 : 48|16@1+ (0.1,0) [0|6553.5] "%"  PC

BO_ 2417356388 S2P_Lmt13__36: 8 SBMU
 SG_ S2P_Lmt13_Over_SOC1_36 : 0|16@1+ (0.1,0) [0|6553.5] "%"  PC
 SG_ S2P_Lmt13_Over_SOC2_36 : 16|16@1+ (0.1,0) [0|6553.5] "%"  PC
 SG_ S2P_Lmt13_Over_SOC3_36 : 32|16@1+ (0.1,0) [0|6553.5] "%"  PC
 SG_ S2P_Lmt13_Over_DSOC_36 : 48|16@1+ (0.1,0) [0|6553.5] "%"  PC

BO_ 2417356389 S2P_Lmt13__37: 8 SBMU
 SG_ S2P_Lmt13_Over_SOC1_37 : 0|16@1+ (0.1,0) [0|6553.5] "%"  PC
 SG_ S2P_Lmt13_Over_SOC2_37 : 16|16@1+ (0.1,0) [0|6553.5] "%"  PC
 SG_ S2P_Lmt13_Over_SOC3_37 : 32|16@1+ (0.1,0) [0|6553.5] "%"  PC
 SG_ S2P_Lmt13_Over_DSOC_37 : 48|16@1+ (0.1,0) [0|6553.5] "%"  PC

BO_ 2417356390 S2P_Lmt13__38: 8 SBMU
 SG_ S2P_Lmt13_Over_SOC1_38 : 0|16@1+ (0.1,0) [0|6553.5] "%"  PC
 SG_ S2P_Lmt13_Over_SOC2_38 : 16|16@1+ (0.1,0) [0|6553.5] "%"  PC
 SG_ S2P_Lmt13_Over_SOC3_38 : 32|16@1+ (0.1,0) [0|6553.5] "%"  PC
 SG_ S2P_Lmt13_Over_DSOC_38 : 48|16@1+ (0.1,0) [0|6553.5] "%"  PC

BO_ 2417356391 S2P_Lmt13__39: 8 SBMU
 SG_ S2P_Lmt13_Over_SOC1_39 : 0|16@1+ (0.1,0) [0|6553.5] "%"  PC
 SG_ S2P_Lmt13_Over_SOC2_39 : 16|16@1+ (0.1,0) [0|6553.5] "%"  PC
 SG_ S2P_Lmt13_Over_SOC3_39 : 32|16@1+ (0.1,0) [0|6553.5] "%"  PC
 SG_ S2P_Lmt13_Over_DSOC_39 : 48|16@1+ (0.1,0) [0|6553.5] "%"  PC

BO_ 2417356392 S2P_Lmt13__40: 8 SBMU
 SG_ S2P_Lmt13_Over_SOC1_40 : 0|16@1+ (0.1,0) [0|6553.5] "%"  PC
 SG_ S2P_Lmt13_Over_SOC2_40 : 16|16@1+ (0.1,0) [0|6553.5] "%"  PC
 SG_ S2P_Lmt13_Over_SOC3_40 : 32|16@1+ (0.1,0) [0|6553.5] "%"  PC
 SG_ S2P_Lmt13_Over_DSOC_40 : 48|16@1+ (0.1,0) [0|6553.5] "%"  PC

BO_ 2417356393 S2P_Lmt13__41: 8 SBMU
 SG_ S2P_Lmt13_Over_SOC1_41 : 0|16@1+ (0.1,0) [0|6553.5] "%"  PC
 SG_ S2P_Lmt13_Over_SOC2_41 : 16|16@1+ (0.1,0) [0|6553.5] "%"  PC
 SG_ S2P_Lmt13_Over_SOC3_41 : 32|16@1+ (0.1,0) [0|6553.5] "%"  PC
 SG_ S2P_Lmt13_Over_DSOC_41 : 48|16@1+ (0.1,0) [0|6553.5] "%"  PC

BO_ 2417356394 S2P_Lmt13__42: 8 SBMU
 SG_ S2P_Lmt13_Over_SOC1_42 : 0|16@1+ (0.1,0) [0|6553.5] "%"  PC
 SG_ S2P_Lmt13_Over_SOC2_42 : 16|16@1+ (0.1,0) [0|6553.5] "%"  PC
 SG_ S2P_Lmt13_Over_SOC3_42 : 32|16@1+ (0.1,0) [0|6553.5] "%"  PC
 SG_ S2P_Lmt13_Over_DSOC_42 : 48|16@1+ (0.1,0) [0|6553.5] "%"  PC

BO_ 2417356395 S2P_Lmt13__43: 8 SBMU
 SG_ S2P_Lmt13_Over_SOC1_43 : 0|16@1+ (0.1,0) [0|6553.5] "%"  PC
 SG_ S2P_Lmt13_Over_SOC2_43 : 16|16@1+ (0.1,0) [0|6553.5] "%"  PC
 SG_ S2P_Lmt13_Over_SOC3_43 : 32|16@1+ (0.1,0) [0|6553.5] "%"  PC
 SG_ S2P_Lmt13_Over_DSOC_43 : 48|16@1+ (0.1,0) [0|6553.5] "%"  PC

BO_ 2417356396 S2P_Lmt13__44: 8 SBMU
 SG_ S2P_Lmt13_Over_SOC1_44 : 0|16@1+ (0.1,0) [0|6553.5] "%"  PC
 SG_ S2P_Lmt13_Over_SOC2_44 : 16|16@1+ (0.1,0) [0|6553.5] "%"  PC
 SG_ S2P_Lmt13_Over_SOC3_44 : 32|16@1+ (0.1,0) [0|6553.5] "%"  PC
 SG_ S2P_Lmt13_Over_DSOC_44 : 48|16@1+ (0.1,0) [0|6553.5] "%"  PC

BO_ 2417356397 S2P_Lmt13__45: 8 SBMU
 SG_ S2P_Lmt13_Over_SOC1_45 : 0|16@1+ (0.1,0) [0|6553.5] "%"  PC
 SG_ S2P_Lmt13_Over_SOC2_45 : 16|16@1+ (0.1,0) [0|6553.5] "%"  PC
 SG_ S2P_Lmt13_Over_SOC3_45 : 32|16@1+ (0.1,0) [0|6553.5] "%"  PC
 SG_ S2P_Lmt13_Over_DSOC_45 : 48|16@1+ (0.1,0) [0|6553.5] "%"  PC

BO_ 2417356398 S2P_Lmt13__46: 8 SBMU
 SG_ S2P_Lmt13_Over_SOC1_46 : 0|16@1+ (0.1,0) [0|6553.5] "%"  PC
 SG_ S2P_Lmt13_Over_SOC2_46 : 16|16@1+ (0.1,0) [0|6553.5] "%"  PC
 SG_ S2P_Lmt13_Over_SOC3_46 : 32|16@1+ (0.1,0) [0|6553.5] "%"  PC
 SG_ S2P_Lmt13_Over_DSOC_46 : 48|16@1+ (0.1,0) [0|6553.5] "%"  PC

BO_ 2417356399 S2P_Lmt13__47: 8 SBMU
 SG_ S2P_Lmt13_Over_SOC1_47 : 0|16@1+ (0.1,0) [0|6553.5] "%"  PC
 SG_ S2P_Lmt13_Over_SOC2_47 : 16|16@1+ (0.1,0) [0|6553.5] "%"  PC
 SG_ S2P_Lmt13_Over_SOC3_47 : 32|16@1+ (0.1,0) [0|6553.5] "%"  PC
 SG_ S2P_Lmt13_Over_DSOC_47 : 48|16@1+ (0.1,0) [0|6553.5] "%"  PC

BO_ 2417356400 S2P_Lmt13__48: 8 SBMU
 SG_ S2P_Lmt13_Over_SOC1_48 : 0|16@1+ (0.1,0) [0|6553.5] "%"  PC
 SG_ S2P_Lmt13_Over_SOC2_48 : 16|16@1+ (0.1,0) [0|6553.5] "%"  PC
 SG_ S2P_Lmt13_Over_SOC3_48 : 32|16@1+ (0.1,0) [0|6553.5] "%"  PC
 SG_ S2P_Lmt13_Over_DSOC_48 : 48|16@1+ (0.1,0) [0|6553.5] "%"  PC

BO_ 2417356401 S2P_Lmt13__49: 8 SBMU
 SG_ S2P_Lmt13_Over_SOC1_49 : 0|16@1+ (0.1,0) [0|6553.5] "%"  PC
 SG_ S2P_Lmt13_Over_SOC2_49 : 16|16@1+ (0.1,0) [0|6553.5] "%"  PC
 SG_ S2P_Lmt13_Over_SOC3_49 : 32|16@1+ (0.1,0) [0|6553.5] "%"  PC
 SG_ S2P_Lmt13_Over_DSOC_49 : 48|16@1+ (0.1,0) [0|6553.5] "%"  PC

BO_ 2417356402 S2P_Lmt13__50: 8 SBMU
 SG_ S2P_Lmt13_Over_SOC1_50 : 0|16@1+ (0.1,0) [0|6553.5] "%"  PC
 SG_ S2P_Lmt13_Over_SOC2_50 : 16|16@1+ (0.1,0) [0|6553.5] "%"  PC
 SG_ S2P_Lmt13_Over_SOC3_50 : 32|16@1+ (0.1,0) [0|6553.5] "%"  PC
 SG_ S2P_Lmt13_Over_DSOC_50 : 48|16@1+ (0.1,0) [0|6553.5] "%"  PC

BO_ 2417356403 S2P_Lmt13__51: 8 SBMU
 SG_ S2P_Lmt13_Over_SOC1_51 : 0|16@1+ (0.1,0) [0|6553.5] "%"  PC
 SG_ S2P_Lmt13_Over_SOC2_51 : 16|16@1+ (0.1,0) [0|6553.5] "%"  PC
 SG_ S2P_Lmt13_Over_SOC3_51 : 32|16@1+ (0.1,0) [0|6553.5] "%"  PC
 SG_ S2P_Lmt13_Over_DSOC_51 : 48|16@1+ (0.1,0) [0|6553.5] "%"  PC

BO_ 2417356404 S2P_Lmt13__52: 8 SBMU
 SG_ S2P_Lmt13_Over_SOC1_52 : 0|16@1+ (0.1,0) [0|6553.5] "%"  PC
 SG_ S2P_Lmt13_Over_SOC2_52 : 16|16@1+ (0.1,0) [0|6553.5] "%"  PC
 SG_ S2P_Lmt13_Over_SOC3_52 : 32|16@1+ (0.1,0) [0|6553.5] "%"  PC
 SG_ S2P_Lmt13_Over_DSOC_52 : 48|16@1+ (0.1,0) [0|6553.5] "%"  PC

BO_ 2417356405 S2P_Lmt13__53: 8 SBMU
 SG_ S2P_Lmt13_Over_SOC1_53 : 0|16@1+ (0.1,0) [0|6553.5] "%"  PC
 SG_ S2P_Lmt13_Over_SOC2_53 : 16|16@1+ (0.1,0) [0|6553.5] "%"  PC
 SG_ S2P_Lmt13_Over_SOC3_53 : 32|16@1+ (0.1,0) [0|6553.5] "%"  PC
 SG_ S2P_Lmt13_Over_DSOC_53 : 48|16@1+ (0.1,0) [0|6553.5] "%"  PC

BO_ 2417356406 S2P_Lmt13__54: 8 SBMU
 SG_ S2P_Lmt13_Over_SOC1_54 : 0|16@1+ (0.1,0) [0|6553.5] "%"  PC
 SG_ S2P_Lmt13_Over_SOC2_54 : 16|16@1+ (0.1,0) [0|6553.5] "%"  PC
 SG_ S2P_Lmt13_Over_SOC3_54 : 32|16@1+ (0.1,0) [0|6553.5] "%"  PC
 SG_ S2P_Lmt13_Over_DSOC_54 : 48|16@1+ (0.1,0) [0|6553.5] "%"  PC

BO_ 2417356407 S2P_Lmt13__55: 8 SBMU
 SG_ S2P_Lmt13_Over_SOC1_55 : 0|16@1+ (0.1,0) [0|6553.5] "%"  PC
 SG_ S2P_Lmt13_Over_SOC2_55 : 16|16@1+ (0.1,0) [0|6553.5] "%"  PC
 SG_ S2P_Lmt13_Over_SOC3_55 : 32|16@1+ (0.1,0) [0|6553.5] "%"  PC
 SG_ S2P_Lmt13_Over_DSOC_55 : 48|16@1+ (0.1,0) [0|6553.5] "%"  PC

BO_ 2417356408 S2P_Lmt13__56: 8 SBMU
 SG_ S2P_Lmt13_Over_SOC1_56 : 0|16@1+ (0.1,0) [0|6553.5] "%"  PC
 SG_ S2P_Lmt13_Over_SOC2_56 : 16|16@1+ (0.1,0) [0|6553.5] "%"  PC
 SG_ S2P_Lmt13_Over_SOC3_56 : 32|16@1+ (0.1,0) [0|6553.5] "%"  PC
 SG_ S2P_Lmt13_Over_DSOC_56 : 48|16@1+ (0.1,0) [0|6553.5] "%"  PC

BO_ 2417356409 S2P_Lmt13__57: 8 SBMU
 SG_ S2P_Lmt13_Over_SOC1_57 : 0|16@1+ (0.1,0) [0|6553.5] "%"  PC
 SG_ S2P_Lmt13_Over_SOC2_57 : 16|16@1+ (0.1,0) [0|6553.5] "%"  PC
 SG_ S2P_Lmt13_Over_SOC3_57 : 32|16@1+ (0.1,0) [0|6553.5] "%"  PC
 SG_ S2P_Lmt13_Over_DSOC_57 : 48|16@1+ (0.1,0) [0|6553.5] "%"  PC

BO_ 2417356410 S2P_Lmt13__58: 8 SBMU
 SG_ S2P_Lmt13_Over_SOC1_58 : 0|16@1+ (0.1,0) [0|6553.5] "%"  PC
 SG_ S2P_Lmt13_Over_SOC2_58 : 16|16@1+ (0.1,0) [0|6553.5] "%"  PC
 SG_ S2P_Lmt13_Over_SOC3_58 : 32|16@1+ (0.1,0) [0|6553.5] "%"  PC
 SG_ S2P_Lmt13_Over_DSOC_58 : 48|16@1+ (0.1,0) [0|6553.5] "%"  PC

BO_ 2417356411 S2P_Lmt13__59: 8 SBMU
 SG_ S2P_Lmt13_Over_SOC1_59 : 0|16@1+ (0.1,0) [0|6553.5] "%"  PC
 SG_ S2P_Lmt13_Over_SOC2_59 : 16|16@1+ (0.1,0) [0|6553.5] "%"  PC
 SG_ S2P_Lmt13_Over_SOC3_59 : 32|16@1+ (0.1,0) [0|6553.5] "%"  PC
 SG_ S2P_Lmt13_Over_DSOC_59 : 48|16@1+ (0.1,0) [0|6553.5] "%"  PC

BO_ 2417356412 S2P_Lmt13__60: 8 SBMU
 SG_ S2P_Lmt13_Over_SOC1_60 : 0|16@1+ (0.1,0) [0|6553.5] "%"  PC
 SG_ S2P_Lmt13_Over_SOC2_60 : 16|16@1+ (0.1,0) [0|6553.5] "%"  PC
 SG_ S2P_Lmt13_Over_SOC3_60 : 32|16@1+ (0.1,0) [0|6553.5] "%"  PC
 SG_ S2P_Lmt13_Over_DSOC_60 : 48|16@1+ (0.1,0) [0|6553.5] "%"  PC

BO_ 2417356413 S2P_Lmt13__61: 8 SBMU
 SG_ S2P_Lmt13_Over_SOC1_61 : 0|16@1+ (0.1,0) [0|6553.5] "%"  PC
 SG_ S2P_Lmt13_Over_SOC2_61 : 16|16@1+ (0.1,0) [0|6553.5] "%"  PC
 SG_ S2P_Lmt13_Over_SOC3_61 : 32|16@1+ (0.1,0) [0|6553.5] "%"  PC
 SG_ S2P_Lmt13_Over_DSOC_61 : 48|16@1+ (0.1,0) [0|6553.5] "%"  PC

BO_ 2417356414 S2P_Lmt13__62: 8 SBMU
 SG_ S2P_Lmt13_Over_SOC1_62 : 0|16@1+ (0.1,0) [0|6553.5] "%"  PC
 SG_ S2P_Lmt13_Over_SOC2_62 : 16|16@1+ (0.1,0) [0|6553.5] "%"  PC
 SG_ S2P_Lmt13_Over_SOC3_62 : 32|16@1+ (0.1,0) [0|6553.5] "%"  PC
 SG_ S2P_Lmt13_Over_DSOC_62 : 48|16@1+ (0.1,0) [0|6553.5] "%"  PC

BO_ 2417356415 S2P_Lmt13__63: 8 SBMU
 SG_ S2P_Lmt13_Over_SOC1_63 : 0|16@1+ (0.1,0) [0|6553.5] "%"  PC
 SG_ S2P_Lmt13_Over_SOC2_63 : 16|16@1+ (0.1,0) [0|6553.5] "%"  PC
 SG_ S2P_Lmt13_Over_SOC3_63 : 32|16@1+ (0.1,0) [0|6553.5] "%"  PC
 SG_ S2P_Lmt13_Over_DSOC_63 : 48|16@1+ (0.1,0) [0|6553.5] "%"  PC

BO_ 2417421889 S2P_Lmt14__01: 8 SBMU
 SG_ S2P_Lmt14_Under_SOC1_01 : 0|16@1+ (0.1,0) [0|6553.5] "%"  PC
 SG_ S2P_Lmt14_Under_SOC2_01 : 16|16@1+ (0.1,0) [0|6553.5] "%"  PC
 SG_ S2P_Lmt14_Under_SOC3_01 : 32|16@1+ (0.1,0) [0|6553.5] "%"  PC
 SG_ S2P_Lmt14_Under_DSOC_01 : 48|16@1+ (0.1,0) [0|6553.5] "%"  PC

BO_ 2417421890 S2P_Lmt14__02: 8 SBMU
 SG_ S2P_Lmt14_Under_SOC1_02 : 0|16@1+ (0.1,0) [0|6553.5] "%"  PC
 SG_ S2P_Lmt14_Under_SOC2_02 : 16|16@1+ (0.1,0) [0|6553.5] "%"  PC
 SG_ S2P_Lmt14_Under_SOC3_02 : 32|16@1+ (0.1,0) [0|6553.5] "%"  PC
 SG_ S2P_Lmt14_Under_DSOC_02 : 48|16@1+ (0.1,0) [0|6553.5] "%"  PC

BO_ 2417421891 S2P_Lmt14__03: 8 SBMU
 SG_ S2P_Lmt14_Under_SOC1_03 : 0|16@1+ (0.1,0) [0|6553.5] "%"  PC
 SG_ S2P_Lmt14_Under_SOC2_03 : 16|16@1+ (0.1,0) [0|6553.5] "%"  PC
 SG_ S2P_Lmt14_Under_SOC3_03 : 32|16@1+ (0.1,0) [0|6553.5] "%"  PC
 SG_ S2P_Lmt14_Under_DSOC_03 : 48|16@1+ (0.1,0) [0|6553.5] "%"  PC

BO_ 2417421892 S2P_Lmt14__04: 8 SBMU
 SG_ S2P_Lmt14_Under_SOC1_04 : 0|16@1+ (0.1,0) [0|6553.5] "%"  PC
 SG_ S2P_Lmt14_Under_SOC2_04 : 16|16@1+ (0.1,0) [0|6553.5] "%"  PC
 SG_ S2P_Lmt14_Under_SOC3_04 : 32|16@1+ (0.1,0) [0|6553.5] "%"  PC
 SG_ S2P_Lmt14_Under_DSOC_04 : 48|16@1+ (0.1,0) [0|6553.5] "%"  PC

BO_ 2417421893 S2P_Lmt14__05: 8 SBMU
 SG_ S2P_Lmt14_Under_SOC1_05 : 0|16@1+ (0.1,0) [0|6553.5] "%"  PC
 SG_ S2P_Lmt14_Under_SOC2_05 : 16|16@1+ (0.1,0) [0|6553.5] "%"  PC
 SG_ S2P_Lmt14_Under_SOC3_05 : 32|16@1+ (0.1,0) [0|6553.5] "%"  PC
 SG_ S2P_Lmt14_Under_DSOC_05 : 48|16@1+ (0.1,0) [0|6553.5] "%"  PC

BO_ 2417421894 S2P_Lmt14__06: 8 SBMU
 SG_ S2P_Lmt14_Under_SOC1_06 : 0|16@1+ (0.1,0) [0|6553.5] "%"  PC
 SG_ S2P_Lmt14_Under_SOC2_06 : 16|16@1+ (0.1,0) [0|6553.5] "%"  PC
 SG_ S2P_Lmt14_Under_SOC3_06 : 32|16@1+ (0.1,0) [0|6553.5] "%"  PC
 SG_ S2P_Lmt14_Under_DSOC_06 : 48|16@1+ (0.1,0) [0|6553.5] "%"  PC

BO_ 2417421895 S2P_Lmt14__07: 8 SBMU
 SG_ S2P_Lmt14_Under_SOC1_07 : 0|16@1+ (0.1,0) [0|6553.5] "%"  PC
 SG_ S2P_Lmt14_Under_SOC2_07 : 16|16@1+ (0.1,0) [0|6553.5] "%"  PC
 SG_ S2P_Lmt14_Under_SOC3_07 : 32|16@1+ (0.1,0) [0|6553.5] "%"  PC
 SG_ S2P_Lmt14_Under_DSOC_07 : 48|16@1+ (0.1,0) [0|6553.5] "%"  PC

BO_ 2417421896 S2P_Lmt14__08: 8 SBMU
 SG_ S2P_Lmt14_Under_SOC1_08 : 0|16@1+ (0.1,0) [0|6553.5] "%"  PC
 SG_ S2P_Lmt14_Under_SOC2_08 : 16|16@1+ (0.1,0) [0|6553.5] "%"  PC
 SG_ S2P_Lmt14_Under_SOC3_08 : 32|16@1+ (0.1,0) [0|6553.5] "%"  PC
 SG_ S2P_Lmt14_Under_DSOC_08 : 48|16@1+ (0.1,0) [0|6553.5] "%"  PC

BO_ 2417421897 S2P_Lmt14__09: 8 SBMU
 SG_ S2P_Lmt14_Under_SOC1_09 : 0|16@1+ (0.1,0) [0|6553.5] "%"  PC
 SG_ S2P_Lmt14_Under_SOC2_09 : 16|16@1+ (0.1,0) [0|6553.5] "%"  PC
 SG_ S2P_Lmt14_Under_SOC3_09 : 32|16@1+ (0.1,0) [0|6553.5] "%"  PC
 SG_ S2P_Lmt14_Under_DSOC_09 : 48|16@1+ (0.1,0) [0|6553.5] "%"  PC

BO_ 2417421898 S2P_Lmt14__10: 8 SBMU
 SG_ S2P_Lmt14_Under_SOC1_10 : 0|16@1+ (0.1,0) [0|6553.5] "%"  PC
 SG_ S2P_Lmt14_Under_SOC2_10 : 16|16@1+ (0.1,0) [0|6553.5] "%"  PC
 SG_ S2P_Lmt14_Under_SOC3_10 : 32|16@1+ (0.1,0) [0|6553.5] "%"  PC
 SG_ S2P_Lmt14_Under_DSOC_10 : 48|16@1+ (0.1,0) [0|6553.5] "%"  PC

BO_ 2417421899 S2P_Lmt14__11: 8 SBMU
 SG_ S2P_Lmt14_Under_SOC1_11 : 0|16@1+ (0.1,0) [0|6553.5] "%"  PC
 SG_ S2P_Lmt14_Under_SOC2_11 : 16|16@1+ (0.1,0) [0|6553.5] "%"  PC
 SG_ S2P_Lmt14_Under_SOC3_11 : 32|16@1+ (0.1,0) [0|6553.5] "%"  PC
 SG_ S2P_Lmt14_Under_DSOC_11 : 48|16@1+ (0.1,0) [0|6553.5] "%"  PC

BO_ 2417421900 S2P_Lmt14__12: 8 SBMU
 SG_ S2P_Lmt14_Under_SOC1_12 : 0|16@1+ (0.1,0) [0|6553.5] "%"  PC
 SG_ S2P_Lmt14_Under_SOC2_12 : 16|16@1+ (0.1,0) [0|6553.5] "%"  PC
 SG_ S2P_Lmt14_Under_SOC3_12 : 32|16@1+ (0.1,0) [0|6553.5] "%"  PC
 SG_ S2P_Lmt14_Under_DSOC_12 : 48|16@1+ (0.1,0) [0|6553.5] "%"  PC

BO_ 2417421901 S2P_Lmt14__13: 8 SBMU
 SG_ S2P_Lmt14_Under_SOC1_13 : 0|16@1+ (0.1,0) [0|6553.5] "%"  PC
 SG_ S2P_Lmt14_Under_SOC2_13 : 16|16@1+ (0.1,0) [0|6553.5] "%"  PC
 SG_ S2P_Lmt14_Under_SOC3_13 : 32|16@1+ (0.1,0) [0|6553.5] "%"  PC
 SG_ S2P_Lmt14_Under_DSOC_13 : 48|16@1+ (0.1,0) [0|6553.5] "%"  PC

BO_ 2417421902 S2P_Lmt14__14: 8 SBMU
 SG_ S2P_Lmt14_Under_SOC1_14 : 0|16@1+ (0.1,0) [0|6553.5] "%"  PC
 SG_ S2P_Lmt14_Under_SOC2_14 : 16|16@1+ (0.1,0) [0|6553.5] "%"  PC
 SG_ S2P_Lmt14_Under_SOC3_14 : 32|16@1+ (0.1,0) [0|6553.5] "%"  PC
 SG_ S2P_Lmt14_Under_DSOC_14 : 48|16@1+ (0.1,0) [0|6553.5] "%"  PC

BO_ 2417421903 S2P_Lmt14__15: 8 SBMU
 SG_ S2P_Lmt14_Under_SOC1_15 : 0|16@1+ (0.1,0) [0|6553.5] "%"  PC
 SG_ S2P_Lmt14_Under_SOC2_15 : 16|16@1+ (0.1,0) [0|6553.5] "%"  PC
 SG_ S2P_Lmt14_Under_SOC3_15 : 32|16@1+ (0.1,0) [0|6553.5] "%"  PC
 SG_ S2P_Lmt14_Under_DSOC_15 : 48|16@1+ (0.1,0) [0|6553.5] "%"  PC

BO_ 2417421904 S2P_Lmt14__16: 8 SBMU
 SG_ S2P_Lmt14_Under_SOC1_16 : 0|16@1+ (0.1,0) [0|6553.5] "%"  PC
 SG_ S2P_Lmt14_Under_SOC2_16 : 16|16@1+ (0.1,0) [0|6553.5] "%"  PC
 SG_ S2P_Lmt14_Under_SOC3_16 : 32|16@1+ (0.1,0) [0|6553.5] "%"  PC
 SG_ S2P_Lmt14_Under_DSOC_16 : 48|16@1+ (0.1,0) [0|6553.5] "%"  PC

BO_ 2417421905 S2P_Lmt14__17: 8 SBMU
 SG_ S2P_Lmt14_Under_SOC1_17 : 0|16@1+ (0.1,0) [0|6553.5] "%"  PC
 SG_ S2P_Lmt14_Under_SOC2_17 : 16|16@1+ (0.1,0) [0|6553.5] "%"  PC
 SG_ S2P_Lmt14_Under_SOC3_17 : 32|16@1+ (0.1,0) [0|6553.5] "%"  PC
 SG_ S2P_Lmt14_Under_DSOC_17 : 48|16@1+ (0.1,0) [0|6553.5] "%"  PC

BO_ 2417421906 S2P_Lmt14__18: 8 SBMU
 SG_ S2P_Lmt14_Under_SOC1_18 : 0|16@1+ (0.1,0) [0|6553.5] "%"  PC
 SG_ S2P_Lmt14_Under_SOC2_18 : 16|16@1+ (0.1,0) [0|6553.5] "%"  PC
 SG_ S2P_Lmt14_Under_SOC3_18 : 32|16@1+ (0.1,0) [0|6553.5] "%"  PC
 SG_ S2P_Lmt14_Under_DSOC_18 : 48|16@1+ (0.1,0) [0|6553.5] "%"  PC

BO_ 2417421907 S2P_Lmt14__19: 8 SBMU
 SG_ S2P_Lmt14_Under_SOC1_19 : 0|16@1+ (0.1,0) [0|6553.5] "%"  PC
 SG_ S2P_Lmt14_Under_SOC2_19 : 16|16@1+ (0.1,0) [0|6553.5] "%"  PC
 SG_ S2P_Lmt14_Under_SOC3_19 : 32|16@1+ (0.1,0) [0|6553.5] "%"  PC
 SG_ S2P_Lmt14_Under_DSOC_19 : 48|16@1+ (0.1,0) [0|6553.5] "%"  PC

BO_ 2417421908 S2P_Lmt14__20: 8 SBMU
 SG_ S2P_Lmt14_Under_SOC1_20 : 0|16@1+ (0.1,0) [0|6553.5] "%"  PC
 SG_ S2P_Lmt14_Under_SOC2_20 : 16|16@1+ (0.1,0) [0|6553.5] "%"  PC
 SG_ S2P_Lmt14_Under_SOC3_20 : 32|16@1+ (0.1,0) [0|6553.5] "%"  PC
 SG_ S2P_Lmt14_Under_DSOC_20 : 48|16@1+ (0.1,0) [0|6553.5] "%"  PC

BO_ 2417421909 S2P_Lmt14__21: 8 SBMU
 SG_ S2P_Lmt14_Under_SOC1_21 : 0|16@1+ (0.1,0) [0|6553.5] "%"  PC
 SG_ S2P_Lmt14_Under_SOC2_21 : 16|16@1+ (0.1,0) [0|6553.5] "%"  PC
 SG_ S2P_Lmt14_Under_SOC3_21 : 32|16@1+ (0.1,0) [0|6553.5] "%"  PC
 SG_ S2P_Lmt14_Under_DSOC_21 : 48|16@1+ (0.1,0) [0|6553.5] "%"  PC

BO_ 2417421910 S2P_Lmt14__22: 8 SBMU
 SG_ S2P_Lmt14_Under_SOC1_22 : 0|16@1+ (0.1,0) [0|6553.5] "%"  PC
 SG_ S2P_Lmt14_Under_SOC2_22 : 16|16@1+ (0.1,0) [0|6553.5] "%"  PC
 SG_ S2P_Lmt14_Under_SOC3_22 : 32|16@1+ (0.1,0) [0|6553.5] "%"  PC
 SG_ S2P_Lmt14_Under_DSOC_22 : 48|16@1+ (0.1,0) [0|6553.5] "%"  PC

BO_ 2417421911 S2P_Lmt14__23: 8 SBMU
 SG_ S2P_Lmt14_Under_SOC1_23 : 0|16@1+ (0.1,0) [0|6553.5] "%"  PC
 SG_ S2P_Lmt14_Under_SOC2_23 : 16|16@1+ (0.1,0) [0|6553.5] "%"  PC
 SG_ S2P_Lmt14_Under_SOC3_23 : 32|16@1+ (0.1,0) [0|6553.5] "%"  PC
 SG_ S2P_Lmt14_Under_DSOC_23 : 48|16@1+ (0.1,0) [0|6553.5] "%"  PC

BO_ 2417421912 S2P_Lmt14__24: 8 SBMU
 SG_ S2P_Lmt14_Under_SOC1_24 : 0|16@1+ (0.1,0) [0|6553.5] "%"  PC
 SG_ S2P_Lmt14_Under_SOC2_24 : 16|16@1+ (0.1,0) [0|6553.5] "%"  PC
 SG_ S2P_Lmt14_Under_SOC3_24 : 32|16@1+ (0.1,0) [0|6553.5] "%"  PC
 SG_ S2P_Lmt14_Under_DSOC_24 : 48|16@1+ (0.1,0) [0|6553.5] "%"  PC

BO_ 2417421913 S2P_Lmt14__25: 8 SBMU
 SG_ S2P_Lmt14_Under_SOC1_25 : 0|16@1+ (0.1,0) [0|6553.5] "%"  PC
 SG_ S2P_Lmt14_Under_SOC2_25 : 16|16@1+ (0.1,0) [0|6553.5] "%"  PC
 SG_ S2P_Lmt14_Under_SOC3_25 : 32|16@1+ (0.1,0) [0|6553.5] "%"  PC
 SG_ S2P_Lmt14_Under_DSOC_25 : 48|16@1+ (0.1,0) [0|6553.5] "%"  PC

BO_ 2417421914 S2P_Lmt14__26: 8 SBMU
 SG_ S2P_Lmt14_Under_SOC1_26 : 0|16@1+ (0.1,0) [0|6553.5] "%"  PC
 SG_ S2P_Lmt14_Under_SOC2_26 : 16|16@1+ (0.1,0) [0|6553.5] "%"  PC
 SG_ S2P_Lmt14_Under_SOC3_26 : 32|16@1+ (0.1,0) [0|6553.5] "%"  PC
 SG_ S2P_Lmt14_Under_DSOC_26 : 48|16@1+ (0.1,0) [0|6553.5] "%"  PC

BO_ 2417421915 S2P_Lmt14__27: 8 SBMU
 SG_ S2P_Lmt14_Under_SOC1_27 : 0|16@1+ (0.1,0) [0|6553.5] "%"  PC
 SG_ S2P_Lmt14_Under_SOC2_27 : 16|16@1+ (0.1,0) [0|6553.5] "%"  PC
 SG_ S2P_Lmt14_Under_SOC3_27 : 32|16@1+ (0.1,0) [0|6553.5] "%"  PC
 SG_ S2P_Lmt14_Under_DSOC_27 : 48|16@1+ (0.1,0) [0|6553.5] "%"  PC

BO_ 2417421916 S2P_Lmt14__28: 8 SBMU
 SG_ S2P_Lmt14_Under_SOC1_28 : 0|16@1+ (0.1,0) [0|6553.5] "%"  PC
 SG_ S2P_Lmt14_Under_SOC2_28 : 16|16@1+ (0.1,0) [0|6553.5] "%"  PC
 SG_ S2P_Lmt14_Under_SOC3_28 : 32|16@1+ (0.1,0) [0|6553.5] "%"  PC
 SG_ S2P_Lmt14_Under_DSOC_28 : 48|16@1+ (0.1,0) [0|6553.5] "%"  PC

BO_ 2417421917 S2P_Lmt14__29: 8 SBMU
 SG_ S2P_Lmt14_Under_SOC1_29 : 0|16@1+ (0.1,0) [0|6553.5] "%"  PC
 SG_ S2P_Lmt14_Under_SOC2_29 : 16|16@1+ (0.1,0) [0|6553.5] "%"  PC
 SG_ S2P_Lmt14_Under_SOC3_29 : 32|16@1+ (0.1,0) [0|6553.5] "%"  PC
 SG_ S2P_Lmt14_Under_DSOC_29 : 48|16@1+ (0.1,0) [0|6553.5] "%"  PC

BO_ 2417421918 S2P_Lmt14__30: 8 SBMU
 SG_ S2P_Lmt14_Under_SOC1_30 : 0|16@1+ (0.1,0) [0|6553.5] "%"  PC
 SG_ S2P_Lmt14_Under_SOC2_30 : 16|16@1+ (0.1,0) [0|6553.5] "%"  PC
 SG_ S2P_Lmt14_Under_SOC3_30 : 32|16@1+ (0.1,0) [0|6553.5] "%"  PC
 SG_ S2P_Lmt14_Under_DSOC_30 : 48|16@1+ (0.1,0) [0|6553.5] "%"  PC

BO_ 2417421919 S2P_Lmt14__31: 8 SBMU
 SG_ S2P_Lmt14_Under_SOC1_31 : 0|16@1+ (0.1,0) [0|6553.5] "%"  PC
 SG_ S2P_Lmt14_Under_SOC2_31 : 16|16@1+ (0.1,0) [0|6553.5] "%"  PC
 SG_ S2P_Lmt14_Under_SOC3_31 : 32|16@1+ (0.1,0) [0|6553.5] "%"  PC
 SG_ S2P_Lmt14_Under_DSOC_31 : 48|16@1+ (0.1,0) [0|6553.5] "%"  PC

BO_ 2417421920 S2P_Lmt14__32: 8 SBMU
 SG_ S2P_Lmt14_Under_SOC1_32 : 0|16@1+ (0.1,0) [0|6553.5] "%"  PC
 SG_ S2P_Lmt14_Under_SOC2_32 : 16|16@1+ (0.1,0) [0|6553.5] "%"  PC
 SG_ S2P_Lmt14_Under_SOC3_32 : 32|16@1+ (0.1,0) [0|6553.5] "%"  PC
 SG_ S2P_Lmt14_Under_DSOC_32 : 48|16@1+ (0.1,0) [0|6553.5] "%"  PC

BO_ 2417421921 S2P_Lmt14__33: 8 SBMU
 SG_ S2P_Lmt14_Under_SOC1_33 : 0|16@1+ (0.1,0) [0|6553.5] "%"  PC
 SG_ S2P_Lmt14_Under_SOC2_33 : 16|16@1+ (0.1,0) [0|6553.5] "%"  PC
 SG_ S2P_Lmt14_Under_SOC3_33 : 32|16@1+ (0.1,0) [0|6553.5] "%"  PC
 SG_ S2P_Lmt14_Under_DSOC_33 : 48|16@1+ (0.1,0) [0|6553.5] "%"  PC

BO_ 2417421922 S2P_Lmt14__34: 8 SBMU
 SG_ S2P_Lmt14_Under_SOC1_34 : 0|16@1+ (0.1,0) [0|6553.5] "%"  PC
 SG_ S2P_Lmt14_Under_SOC2_34 : 16|16@1+ (0.1,0) [0|6553.5] "%"  PC
 SG_ S2P_Lmt14_Under_SOC3_34 : 32|16@1+ (0.1,0) [0|6553.5] "%"  PC
 SG_ S2P_Lmt14_Under_DSOC_34 : 48|16@1+ (0.1,0) [0|6553.5] "%"  PC

BO_ 2417421923 S2P_Lmt14__35: 8 SBMU
 SG_ S2P_Lmt14_Under_SOC1_35 : 0|16@1+ (0.1,0) [0|6553.5] "%"  PC
 SG_ S2P_Lmt14_Under_SOC2_35 : 16|16@1+ (0.1,0) [0|6553.5] "%"  PC
 SG_ S2P_Lmt14_Under_SOC3_35 : 32|16@1+ (0.1,0) [0|6553.5] "%"  PC
 SG_ S2P_Lmt14_Under_DSOC_35 : 48|16@1+ (0.1,0) [0|6553.5] "%"  PC

BO_ 2417421924 S2P_Lmt14__36: 8 SBMU
 SG_ S2P_Lmt14_Under_SOC1_36 : 0|16@1+ (0.1,0) [0|6553.5] "%"  PC
 SG_ S2P_Lmt14_Under_SOC2_36 : 16|16@1+ (0.1,0) [0|6553.5] "%"  PC
 SG_ S2P_Lmt14_Under_SOC3_36 : 32|16@1+ (0.1,0) [0|6553.5] "%"  PC
 SG_ S2P_Lmt14_Under_DSOC_36 : 48|16@1+ (0.1,0) [0|6553.5] "%"  PC

BO_ 2417421925 S2P_Lmt14__37: 8 SBMU
 SG_ S2P_Lmt14_Under_SOC1_37 : 0|16@1+ (0.1,0) [0|6553.5] "%"  PC
 SG_ S2P_Lmt14_Under_SOC2_37 : 16|16@1+ (0.1,0) [0|6553.5] "%"  PC
 SG_ S2P_Lmt14_Under_SOC3_37 : 32|16@1+ (0.1,0) [0|6553.5] "%"  PC
 SG_ S2P_Lmt14_Under_DSOC_37 : 48|16@1+ (0.1,0) [0|6553.5] "%"  PC

BO_ 2417421926 S2P_Lmt14__38: 8 SBMU
 SG_ S2P_Lmt14_Under_SOC1_38 : 0|16@1+ (0.1,0) [0|6553.5] "%"  PC
 SG_ S2P_Lmt14_Under_SOC2_38 : 16|16@1+ (0.1,0) [0|6553.5] "%"  PC
 SG_ S2P_Lmt14_Under_SOC3_38 : 32|16@1+ (0.1,0) [0|6553.5] "%"  PC
 SG_ S2P_Lmt14_Under_DSOC_38 : 48|16@1+ (0.1,0) [0|6553.5] "%"  PC

BO_ 2417421927 S2P_Lmt14__39: 8 SBMU
 SG_ S2P_Lmt14_Under_SOC1_39 : 0|16@1+ (0.1,0) [0|6553.5] "%"  PC
 SG_ S2P_Lmt14_Under_SOC2_39 : 16|16@1+ (0.1,0) [0|6553.5] "%"  PC
 SG_ S2P_Lmt14_Under_SOC3_39 : 32|16@1+ (0.1,0) [0|6553.5] "%"  PC
 SG_ S2P_Lmt14_Under_DSOC_39 : 48|16@1+ (0.1,0) [0|6553.5] "%"  PC

BO_ 2417421928 S2P_Lmt14__40: 8 SBMU
 SG_ S2P_Lmt14_Under_SOC1_40 : 0|16@1+ (0.1,0) [0|6553.5] "%"  PC
 SG_ S2P_Lmt14_Under_SOC2_40 : 16|16@1+ (0.1,0) [0|6553.5] "%"  PC
 SG_ S2P_Lmt14_Under_SOC3_40 : 32|16@1+ (0.1,0) [0|6553.5] "%"  PC
 SG_ S2P_Lmt14_Under_DSOC_40 : 48|16@1+ (0.1,0) [0|6553.5] "%"  PC

BO_ 2417421929 S2P_Lmt14__41: 8 SBMU
 SG_ S2P_Lmt14_Under_SOC1_41 : 0|16@1+ (0.1,0) [0|6553.5] "%"  PC
 SG_ S2P_Lmt14_Under_SOC2_41 : 16|16@1+ (0.1,0) [0|6553.5] "%"  PC
 SG_ S2P_Lmt14_Under_SOC3_41 : 32|16@1+ (0.1,0) [0|6553.5] "%"  PC
 SG_ S2P_Lmt14_Under_DSOC_41 : 48|16@1+ (0.1,0) [0|6553.5] "%"  PC

BO_ 2417421930 S2P_Lmt14__42: 8 SBMU
 SG_ S2P_Lmt14_Under_SOC1_42 : 0|16@1+ (0.1,0) [0|6553.5] "%"  PC
 SG_ S2P_Lmt14_Under_SOC2_42 : 16|16@1+ (0.1,0) [0|6553.5] "%"  PC
 SG_ S2P_Lmt14_Under_SOC3_42 : 32|16@1+ (0.1,0) [0|6553.5] "%"  PC
 SG_ S2P_Lmt14_Under_DSOC_42 : 48|16@1+ (0.1,0) [0|6553.5] "%"  PC

BO_ 2417421931 S2P_Lmt14__43: 8 SBMU
 SG_ S2P_Lmt14_Under_SOC1_43 : 0|16@1+ (0.1,0) [0|6553.5] "%"  PC
 SG_ S2P_Lmt14_Under_SOC2_43 : 16|16@1+ (0.1,0) [0|6553.5] "%"  PC
 SG_ S2P_Lmt14_Under_SOC3_43 : 32|16@1+ (0.1,0) [0|6553.5] "%"  PC
 SG_ S2P_Lmt14_Under_DSOC_43 : 48|16@1+ (0.1,0) [0|6553.5] "%"  PC

BO_ 2417421932 S2P_Lmt14__44: 8 SBMU
 SG_ S2P_Lmt14_Under_SOC1_44 : 0|16@1+ (0.1,0) [0|6553.5] "%"  PC
 SG_ S2P_Lmt14_Under_SOC2_44 : 16|16@1+ (0.1,0) [0|6553.5] "%"  PC
 SG_ S2P_Lmt14_Under_SOC3_44 : 32|16@1+ (0.1,0) [0|6553.5] "%"  PC
 SG_ S2P_Lmt14_Under_DSOC_44 : 48|16@1+ (0.1,0) [0|6553.5] "%"  PC

BO_ 2417421933 S2P_Lmt14__45: 8 SBMU
 SG_ S2P_Lmt14_Under_SOC1_45 : 0|16@1+ (0.1,0) [0|6553.5] "%"  PC
 SG_ S2P_Lmt14_Under_SOC2_45 : 16|16@1+ (0.1,0) [0|6553.5] "%"  PC
 SG_ S2P_Lmt14_Under_SOC3_45 : 32|16@1+ (0.1,0) [0|6553.5] "%"  PC
 SG_ S2P_Lmt14_Under_DSOC_45 : 48|16@1+ (0.1,0) [0|6553.5] "%"  PC

BO_ 2417421934 S2P_Lmt14__46: 8 SBMU
 SG_ S2P_Lmt14_Under_SOC1_46 : 0|16@1+ (0.1,0) [0|6553.5] "%"  PC
 SG_ S2P_Lmt14_Under_SOC2_46 : 16|16@1+ (0.1,0) [0|6553.5] "%"  PC
 SG_ S2P_Lmt14_Under_SOC3_46 : 32|16@1+ (0.1,0) [0|6553.5] "%"  PC
 SG_ S2P_Lmt14_Under_DSOC_46 : 48|16@1+ (0.1,0) [0|6553.5] "%"  PC

BO_ 2417421935 S2P_Lmt14__47: 8 SBMU
 SG_ S2P_Lmt14_Under_SOC1_47 : 0|16@1+ (0.1,0) [0|6553.5] "%"  PC
 SG_ S2P_Lmt14_Under_SOC2_47 : 16|16@1+ (0.1,0) [0|6553.5] "%"  PC
 SG_ S2P_Lmt14_Under_SOC3_47 : 32|16@1+ (0.1,0) [0|6553.5] "%"  PC
 SG_ S2P_Lmt14_Under_DSOC_47 : 48|16@1+ (0.1,0) [0|6553.5] "%"  PC

BO_ 2417421936 S2P_Lmt14__48: 8 SBMU
 SG_ S2P_Lmt14_Under_SOC1_48 : 0|16@1+ (0.1,0) [0|6553.5] "%"  PC
 SG_ S2P_Lmt14_Under_SOC2_48 : 16|16@1+ (0.1,0) [0|6553.5] "%"  PC
 SG_ S2P_Lmt14_Under_SOC3_48 : 32|16@1+ (0.1,0) [0|6553.5] "%"  PC
 SG_ S2P_Lmt14_Under_DSOC_48 : 48|16@1+ (0.1,0) [0|6553.5] "%"  PC

BO_ 2417421937 S2P_Lmt14__49: 8 SBMU
 SG_ S2P_Lmt14_Under_SOC1_49 : 0|16@1+ (0.1,0) [0|6553.5] "%"  PC
 SG_ S2P_Lmt14_Under_SOC2_49 : 16|16@1+ (0.1,0) [0|6553.5] "%"  PC
 SG_ S2P_Lmt14_Under_SOC3_49 : 32|16@1+ (0.1,0) [0|6553.5] "%"  PC
 SG_ S2P_Lmt14_Under_DSOC_49 : 48|16@1+ (0.1,0) [0|6553.5] "%"  PC

BO_ 2417421938 S2P_Lmt14__50: 8 SBMU
 SG_ S2P_Lmt14_Under_SOC1_50 : 0|16@1+ (0.1,0) [0|6553.5] "%"  PC
 SG_ S2P_Lmt14_Under_SOC2_50 : 16|16@1+ (0.1,0) [0|6553.5] "%"  PC
 SG_ S2P_Lmt14_Under_SOC3_50 : 32|16@1+ (0.1,0) [0|6553.5] "%"  PC
 SG_ S2P_Lmt14_Under_DSOC_50 : 48|16@1+ (0.1,0) [0|6553.5] "%"  PC

BO_ 2417421939 S2P_Lmt14__51: 8 SBMU
 SG_ S2P_Lmt14_Under_SOC1_51 : 0|16@1+ (0.1,0) [0|6553.5] "%"  PC
 SG_ S2P_Lmt14_Under_SOC2_51 : 16|16@1+ (0.1,0) [0|6553.5] "%"  PC
 SG_ S2P_Lmt14_Under_SOC3_51 : 32|16@1+ (0.1,0) [0|6553.5] "%"  PC
 SG_ S2P_Lmt14_Under_DSOC_51 : 48|16@1+ (0.1,0) [0|6553.5] "%"  PC

BO_ 2417421940 S2P_Lmt14__52: 8 SBMU
 SG_ S2P_Lmt14_Under_SOC1_52 : 0|16@1+ (0.1,0) [0|6553.5] "%"  PC
 SG_ S2P_Lmt14_Under_SOC2_52 : 16|16@1+ (0.1,0) [0|6553.5] "%"  PC
 SG_ S2P_Lmt14_Under_SOC3_52 : 32|16@1+ (0.1,0) [0|6553.5] "%"  PC
 SG_ S2P_Lmt14_Under_DSOC_52 : 48|16@1+ (0.1,0) [0|6553.5] "%"  PC

BO_ 2417421941 S2P_Lmt14__53: 8 SBMU
 SG_ S2P_Lmt14_Under_SOC1_53 : 0|16@1+ (0.1,0) [0|6553.5] "%"  PC
 SG_ S2P_Lmt14_Under_SOC2_53 : 16|16@1+ (0.1,0) [0|6553.5] "%"  PC
 SG_ S2P_Lmt14_Under_SOC3_53 : 32|16@1+ (0.1,0) [0|6553.5] "%"  PC
 SG_ S2P_Lmt14_Under_DSOC_53 : 48|16@1+ (0.1,0) [0|6553.5] "%"  PC

BO_ 2417421942 S2P_Lmt14__54: 8 SBMU
 SG_ S2P_Lmt14_Under_SOC1_54 : 0|16@1+ (0.1,0) [0|6553.5] "%"  PC
 SG_ S2P_Lmt14_Under_SOC2_54 : 16|16@1+ (0.1,0) [0|6553.5] "%"  PC
 SG_ S2P_Lmt14_Under_SOC3_54 : 32|16@1+ (0.1,0) [0|6553.5] "%"  PC
 SG_ S2P_Lmt14_Under_DSOC_54 : 48|16@1+ (0.1,0) [0|6553.5] "%"  PC

BO_ 2417421943 S2P_Lmt14__55: 8 SBMU
 SG_ S2P_Lmt14_Under_SOC1_55 : 0|16@1+ (0.1,0) [0|6553.5] "%"  PC
 SG_ S2P_Lmt14_Under_SOC2_55 : 16|16@1+ (0.1,0) [0|6553.5] "%"  PC
 SG_ S2P_Lmt14_Under_SOC3_55 : 32|16@1+ (0.1,0) [0|6553.5] "%"  PC
 SG_ S2P_Lmt14_Under_DSOC_55 : 48|16@1+ (0.1,0) [0|6553.5] "%"  PC

BO_ 2417421944 S2P_Lmt14__56: 8 SBMU
 SG_ S2P_Lmt14_Under_SOC1_56 : 0|16@1+ (0.1,0) [0|6553.5] "%"  PC
 SG_ S2P_Lmt14_Under_SOC2_56 : 16|16@1+ (0.1,0) [0|6553.5] "%"  PC
 SG_ S2P_Lmt14_Under_SOC3_56 : 32|16@1+ (0.1,0) [0|6553.5] "%"  PC
 SG_ S2P_Lmt14_Under_DSOC_56 : 48|16@1+ (0.1,0) [0|6553.5] "%"  PC

BO_ 2417421945 S2P_Lmt14__57: 8 SBMU
 SG_ S2P_Lmt14_Under_SOC1_57 : 0|16@1+ (0.1,0) [0|6553.5] "%"  PC
 SG_ S2P_Lmt14_Under_SOC2_57 : 16|16@1+ (0.1,0) [0|6553.5] "%"  PC
 SG_ S2P_Lmt14_Under_SOC3_57 : 32|16@1+ (0.1,0) [0|6553.5] "%"  PC
 SG_ S2P_Lmt14_Under_DSOC_57 : 48|16@1+ (0.1,0) [0|6553.5] "%"  PC

BO_ 2417421946 S2P_Lmt14__58: 8 SBMU
 SG_ S2P_Lmt14_Under_SOC1_58 : 0|16@1+ (0.1,0) [0|6553.5] "%"  PC
 SG_ S2P_Lmt14_Under_SOC2_58 : 16|16@1+ (0.1,0) [0|6553.5] "%"  PC
 SG_ S2P_Lmt14_Under_SOC3_58 : 32|16@1+ (0.1,0) [0|6553.5] "%"  PC
 SG_ S2P_Lmt14_Under_DSOC_58 : 48|16@1+ (0.1,0) [0|6553.5] "%"  PC

BO_ 2417421947 S2P_Lmt14__59: 8 SBMU
 SG_ S2P_Lmt14_Under_SOC1_59 : 0|16@1+ (0.1,0) [0|6553.5] "%"  PC
 SG_ S2P_Lmt14_Under_SOC2_59 : 16|16@1+ (0.1,0) [0|6553.5] "%"  PC
 SG_ S2P_Lmt14_Under_SOC3_59 : 32|16@1+ (0.1,0) [0|6553.5] "%"  PC
 SG_ S2P_Lmt14_Under_DSOC_59 : 48|16@1+ (0.1,0) [0|6553.5] "%"  PC

BO_ 2417421948 S2P_Lmt14__60: 8 SBMU
 SG_ S2P_Lmt14_Under_SOC1_60 : 0|16@1+ (0.1,0) [0|6553.5] "%"  PC
 SG_ S2P_Lmt14_Under_SOC2_60 : 16|16@1+ (0.1,0) [0|6553.5] "%"  PC
 SG_ S2P_Lmt14_Under_SOC3_60 : 32|16@1+ (0.1,0) [0|6553.5] "%"  PC
 SG_ S2P_Lmt14_Under_DSOC_60 : 48|16@1+ (0.1,0) [0|6553.5] "%"  PC

BO_ 2417421949 S2P_Lmt14__61: 8 SBMU
 SG_ S2P_Lmt14_Under_SOC1_61 : 0|16@1+ (0.1,0) [0|6553.5] "%"  PC
 SG_ S2P_Lmt14_Under_SOC2_61 : 16|16@1+ (0.1,0) [0|6553.5] "%"  PC
 SG_ S2P_Lmt14_Under_SOC3_61 : 32|16@1+ (0.1,0) [0|6553.5] "%"  PC
 SG_ S2P_Lmt14_Under_DSOC_61 : 48|16@1+ (0.1,0) [0|6553.5] "%"  PC

BO_ 2417421950 S2P_Lmt14__62: 8 SBMU
 SG_ S2P_Lmt14_Under_SOC1_62 : 0|16@1+ (0.1,0) [0|6553.5] "%"  PC
 SG_ S2P_Lmt14_Under_SOC2_62 : 16|16@1+ (0.1,0) [0|6553.5] "%"  PC
 SG_ S2P_Lmt14_Under_SOC3_62 : 32|16@1+ (0.1,0) [0|6553.5] "%"  PC
 SG_ S2P_Lmt14_Under_DSOC_62 : 48|16@1+ (0.1,0) [0|6553.5] "%"  PC

BO_ 2417421951 S2P_Lmt14__63: 8 SBMU
 SG_ S2P_Lmt14_Under_SOC1_63 : 0|16@1+ (0.1,0) [0|6553.5] "%"  PC
 SG_ S2P_Lmt14_Under_SOC2_63 : 16|16@1+ (0.1,0) [0|6553.5] "%"  PC
 SG_ S2P_Lmt14_Under_SOC3_63 : 32|16@1+ (0.1,0) [0|6553.5] "%"  PC
 SG_ S2P_Lmt14_Under_DSOC_63 : 48|16@1+ (0.1,0) [0|6553.5] "%"  PC

BO_ 2197352447 S2P_VersionData: 8 SBMU
 SG_ S2P_VerData_Data0 : 0|8@1+ (1,0) [0|255] "%"  PC
 SG_ S2P_VerData_Data1 : 8|8@1+ (1,0) [0|255] "%"  PC
 SG_ S2P_VerData_Data2 : 16|8@1+ (1,0) [0|255] "%"  PC
 SG_ S2P_VerData_Data3 : 24|8@1+ (1,0) [0|255] "%"  PC
 SG_ S2P_VerData_Data4 : 32|8@1+ (1,0) [0|255] "%"  PC
 SG_ S2P_VerData_Data5 : 40|8@1+ (1,0) [0|255] "%"  PC
 SG_ S2P_VerData_Data6 : 48|8@1+ (1,0) [0|255] "%"  PC
 SG_ S2P_VerData_Data7 : 56|8@1+ (1,0) [0|255] "%"  PC

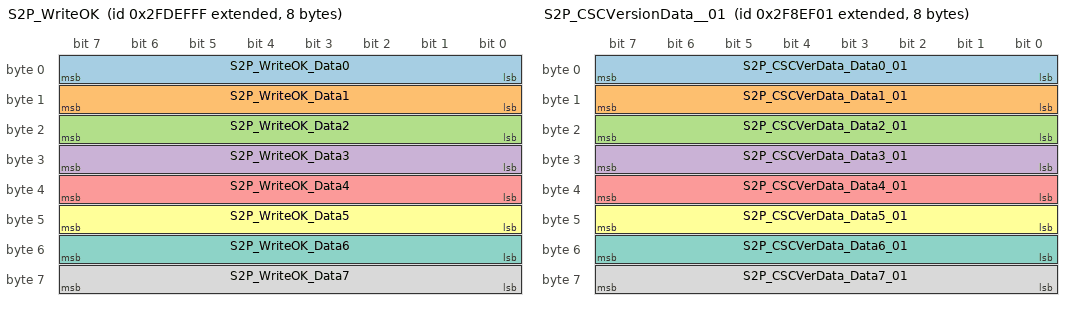
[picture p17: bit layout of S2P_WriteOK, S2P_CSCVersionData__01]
BO_ 2197680127 S2P_WriteOK: 8 SBMU
 SG_ S2P_WriteOK_Data0 : 0|8@1+ (1,0) [0|255] "%"  PC
 SG_ S2P_WriteOK_Data1 : 8|8@1+ (1,0) [0|255] "%"  PC
 SG_ S2P_WriteOK_Data2 : 16|8@1+ (1,0) [0|255] "%"  PC
 SG_ S2P_WriteOK_Data3 : 24|8@1+ (1,0) [0|255] "%"  PC
 SG_ S2P_WriteOK_Data4 : 32|8@1+ (1,0) [0|255] "%"  PC
 SG_ S2P_WriteOK_Data5 : 40|8@1+ (1,0) [0|255] "%"  PC
 SG_ S2P_WriteOK_Data6 : 48|8@1+ (1,0) [0|255] "%"  PC
 SG_ S2P_WriteOK_Data7 : 56|8@1+ (1,0) [0|255] "%"  PC

BO_ 2197352193 S2P_CSCVersionData__01: 8 SBMU
 SG_ S2P_CSCVerData_Data0_01 : 0|8@1+ (1,0) [0|255] "%"  PC
 SG_ S2P_CSCVerData_Data1_01 : 8|8@1+ (1,0) [0|255] "%"  PC
 SG_ S2P_CSCVerData_Data2_01 : 16|8@1+ (1,0) [0|255] "%"  PC
 SG_ S2P_CSCVerData_Data3_01 : 24|8@1+ (1,0) [0|255] "%"  PC
 SG_ S2P_CSCVerData_Data4_01 : 32|8@1+ (1,0) [0|255] "%"  PC
 SG_ S2P_CSCVerData_Data5_01 : 40|8@1+ (1,0) [0|255] "%"  PC
 SG_ S2P_CSCVerData_Data6_01 : 48|8@1+ (1,0) [0|255] "%"  PC
 SG_ S2P_CSCVerData_Data7_01 : 56|8@1+ (1,0) [0|255] "%"  PC

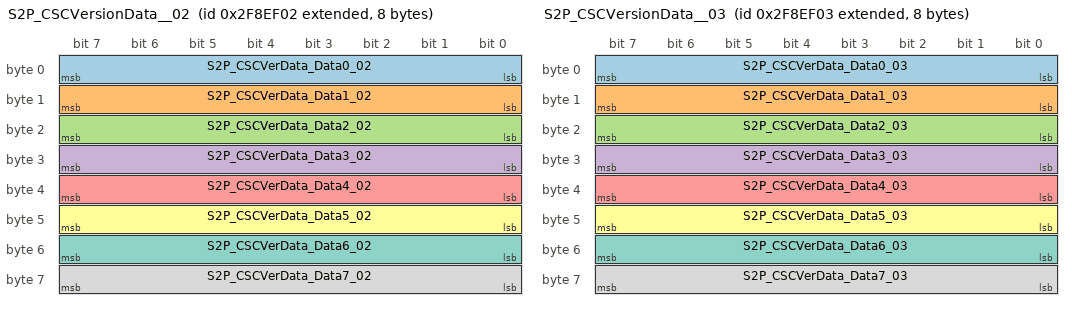
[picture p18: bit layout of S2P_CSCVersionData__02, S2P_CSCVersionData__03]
BO_ 2197352194 S2P_CSCVersionData__02: 8 SBMU
 SG_ S2P_CSCVerData_Data0_02 : 0|8@1+ (1,0) [0|255] "%"  PC
 SG_ S2P_CSCVerData_Data1_02 : 8|8@1+ (1,0) [0|255] "%"  PC
 SG_ S2P_CSCVerData_Data2_02 : 16|8@1+ (1,0) [0|255] "%"  PC
 SG_ S2P_CSCVerData_Data3_02 : 24|8@1+ (1,0) [0|255] "%"  PC
 SG_ S2P_CSCVerData_Data4_02 : 32|8@1+ (1,0) [0|255] "%"  PC
 SG_ S2P_CSCVerData_Data5_02 : 40|8@1+ (1,0) [0|255] "%"  PC
 SG_ S2P_CSCVerData_Data6_02 : 48|8@1+ (1,0) [0|255] "%"  PC
 SG_ S2P_CSCVerData_Data7_02 : 56|8@1+ (1,0) [0|255] "%"  PC

BO_ 2197352195 S2P_CSCVersionData__03: 8 SBMU
 SG_ S2P_CSCVerData_Data0_03 : 0|8@1+ (1,0) [0|255] "%"  PC
 SG_ S2P_CSCVerData_Data1_03 : 8|8@1+ (1,0) [0|255] "%"  PC
 SG_ S2P_CSCVerData_Data2_03 : 16|8@1+ (1,0) [0|255] "%"  PC
 SG_ S2P_CSCVerData_Data3_03 : 24|8@1+ (1,0) [0|255] "%"  PC
 SG_ S2P_CSCVerData_Data4_03 : 32|8@1+ (1,0) [0|255] "%"  PC
 SG_ S2P_CSCVerData_Data5_03 : 40|8@1+ (1,0) [0|255] "%"  PC
 SG_ S2P_CSCVerData_Data6_03 : 48|8@1+ (1,0) [0|255] "%"  PC
 SG_ S2P_CSCVerData_Data7_03 : 56|8@1+ (1,0) [0|255] "%"  PC

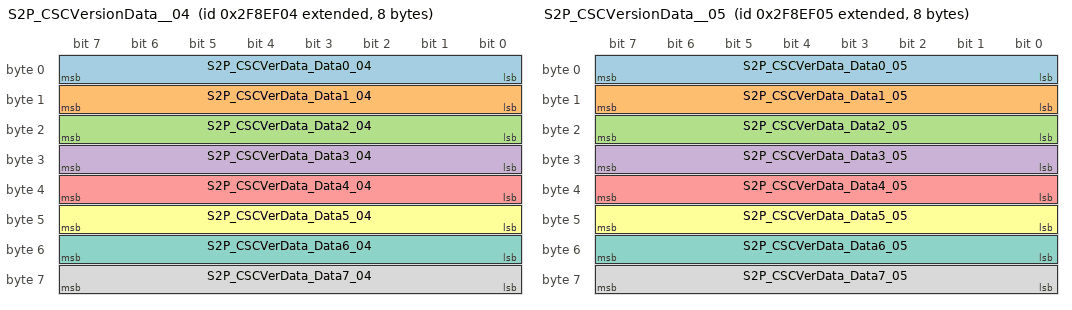
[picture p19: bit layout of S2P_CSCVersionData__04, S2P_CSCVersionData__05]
BO_ 2197352196 S2P_CSCVersionData__04: 8 SBMU
 SG_ S2P_CSCVerData_Data0_04 : 0|8@1+ (1,0) [0|255] "%"  PC
 SG_ S2P_CSCVerData_Data1_04 : 8|8@1+ (1,0) [0|255] "%"  PC
 SG_ S2P_CSCVerData_Data2_04 : 16|8@1+ (1,0) [0|255] "%"  PC
 SG_ S2P_CSCVerData_Data3_04 : 24|8@1+ (1,0) [0|255] "%"  PC
 SG_ S2P_CSCVerData_Data4_04 : 32|8@1+ (1,0) [0|255] "%"  PC
 SG_ S2P_CSCVerData_Data5_04 : 40|8@1+ (1,0) [0|255] "%"  PC
 SG_ S2P_CSCVerData_Data6_04 : 48|8@1+ (1,0) [0|255] "%"  PC
 SG_ S2P_CSCVerData_Data7_04 : 56|8@1+ (1,0) [0|255] "%"  PC

BO_ 2197352197 S2P_CSCVersionData__05: 8 SBMU
 SG_ S2P_CSCVerData_Data0_05 : 0|8@1+ (1,0) [0|255] "%"  PC
 SG_ S2P_CSCVerData_Data1_05 : 8|8@1+ (1,0) [0|255] "%"  PC
 SG_ S2P_CSCVerData_Data2_05 : 16|8@1+ (1,0) [0|255] "%"  PC
 SG_ S2P_CSCVerData_Data3_05 : 24|8@1+ (1,0) [0|255] "%"  PC
 SG_ S2P_CSCVerData_Data4_05 : 32|8@1+ (1,0) [0|255] "%"  PC
 SG_ S2P_CSCVerData_Data5_05 : 40|8@1+ (1,0) [0|255] "%"  PC
 SG_ S2P_CSCVerData_Data6_05 : 48|8@1+ (1,0) [0|255] "%"  PC
 SG_ S2P_CSCVerData_Data7_05 : 56|8@1+ (1,0) [0|255] "%"  PC

CM_ SG_ 2417159784 S2P_Lmt10_Under_Tcell1_40 "电池单体低温一级报警温度";
CM_ SG_ 2417159784 S2P_Lmt10_Under_DTcell1_40 "单体低温1级告警消除回差阈值";
CM_ SG_ 2417159784 S2P_Lmt10_Under_Tcell2_40 "电池单体低温二级报警温度";
CM_ SG_ 2417159784 S2P_Lmt10_Under_DTcell2_40 "单体低温2级告警消除回差阈值";
CM_ SG_ 2417159784 S2P_Lmt10_Under_Tcell3_40 "电池单体低温三级报警温度";
CM_ SG_ 2417159784 S2P_Lmt10_Under_DTcell3_40 "单体低温3级告警消除回差阈值";
CM_ SG_ 2417159785 S2P_Lmt10_Under_Tcell1_41 "电池单体低温一级报警温度";
CM_ SG_ 2417159785 S2P_Lmt10_Under_DTcell1_41 "单体低温1级告警消除回差阈值";
CM_ SG_ 2417159785 S2P_Lmt10_Under_Tcell2_41 "电池单体低温二级报警温度";
CM_ SG_ 2417159785 S2P_Lmt10_Under_DTcell2_41 "单体低温2级告警消除回差阈值";
CM_ SG_ 2417159785 S2P_Lmt10_Under_Tcell3_41 "电池单体低温三级报警温度";
CM_ SG_ 2417159785 S2P_Lmt10_Under_DTcell3_41 "单体低温3级告警消除回差阈值";
CM_ SG_ 2417159786 S2P_Lmt10_Under_Tcell1_42 "电池单体低温一级报警温度";
CM_ SG_ 2417159786 S2P_Lmt10_Under_DTcell1_42 "单体低温1级告警消除回差阈值";
CM_ SG_ 2417159786 S2P_Lmt10_Under_Tcell2_42 "电池单体低温二级报警温度";
CM_ SG_ 2417159786 S2P_Lmt10_Under_DTcell2_42 "单体低温2级告警消除回差阈值";
CM_ SG_ 2417159786 S2P_Lmt10_Under_Tcell3_42 "电池单体低温三级报警温度";
CM_ SG_ 2417159786 S2P_Lmt10_Under_DTcell3_42 "单体低温3级告警消除回差阈值";
CM_ SG_ 2417159787 S2P_Lmt10_Under_Tcell1_43 "电池单体低温一级报警温度";
CM_ SG_ 2417159787 S2P_Lmt10_Under_DTcell1_43 "单体低温1级告警消除回差阈值";
CM_ SG_ 2417159787 S2P_Lmt10_Under_Tcell2_43 "电池单体低温二级报警温度";
CM_ SG_ 2417159787 S2P_Lmt10_Under_DTcell2_43 "单体低温2级告警消除回差阈值";
CM_ SG_ 2417159787 S2P_Lmt10_Under_Tcell3_43 "电池单体低温三级报警温度";
CM_ SG_ 2417159787 S2P_Lmt10_Under_DTcell3_43 "单体低温3级告警消除回差阈值";
CM_ SG_ 2417159788 S2P_Lmt10_Under_Tcell1_44 "电池单体低温一级报警温度";
CM_ SG_ 2417159788 S2P_Lmt10_Under_DTcell1_44 "单体低温1级告警消除回差阈值";
CM_ SG_ 2417159788 S2P_Lmt10_Under_Tcell2_44 "电池单体低温二级报警温度";
CM_ SG_ 2417159788 S2P_Lmt10_Under_DTcell2_44 "单体低温2级告警消除回差阈值";
CM_ SG_ 2417159788 S2P_Lmt10_Under_Tcell3_44 "电池单体低温三级报警温度";
CM_ SG_ 2417159788 S2P_Lmt10_Under_DTcell3_44 "单体低温3级告警消除回差阈值";
CM_ SG_ 2417159789 S2P_Lmt10_Under_Tcell1_45 "电池单体低温一级报警温度";
CM_ SG_ 2417159789 S2P_Lmt10_Under_DTcell1_45 "单体低温1级告警消除回差阈值";
CM_ SG_ 2417159789 S2P_Lmt10_Under_Tcell2_45 "电池单体低温二级报警温度";
CM_ SG_ 2417159789 S2P_Lmt10_Under_DTcell2_45 "单体低温2级告警消除回差阈值";
CM_ SG_ 2417159789 S2P_Lmt10_Under_Tcell3_45 "电池单体低温三级报警温度";
CM_ SG_ 2417159789 S2P_Lmt10_Under_DTcell3_45 "单体低温3级告警消除回差阈值";
CM_ SG_ 2417159790 S2P_Lmt10_Under_Tcell1_46 "电池单体低温一级报警温度";
CM_ SG_ 2417159790 S2P_Lmt10_Under_DTcell1_46 "单体低温1级告警消除回差阈值";
CM_ SG_ 2417159790 S2P_Lmt10_Under_Tcell2_46 "电池单体低温二级报警温度";
CM_ SG_ 2417159790 S2P_Lmt10_Under_DTcell2_46 "单体低温2级告警消除回差阈值";
CM_ SG_ 2417159790 S2P_Lmt10_Under_Tcell3_46 "电池单体低温三级报警温度";
CM_ SG_ 2417159790 S2P_Lmt10_Under_DTcell3_46 "单体低温3级告警消除回差阈值";
CM_ SG_ 2417159791 S2P_Lmt10_Under_Tcell1_47 "电池单体低温一级报警温度";
CM_ SG_ 2417159791 S2P_Lmt10_Under_DTcell1_47 "单体低温1级告警消除回差阈值";
CM_ SG_ 2417159791 S2P_Lmt10_Under_Tcell2_47 "电池单体低温二级报警温度";
CM_ SG_ 2417159791 S2P_Lmt10_Under_DTcell2_47 "单体低温2级告警消除回差阈值";
CM_ SG_ 2417159791 S2P_Lmt10_Under_Tcell3_47 "电池单体低温三级报警温度";
CM_ SG_ 2417159791 S2P_Lmt10_Under_DTcell3_47 "单体低温3级告警消除回差阈值";
CM_ SG_ 2417159792 S2P_Lmt10_Under_Tcell1_48 "电池单体低温一级报警温度";
CM_ SG_ 2417159792 S2P_Lmt10_Under_DTcell1_48 "单体低温1级告警消除回差阈值";
CM_ SG_ 2417159792 S2P_Lmt10_Under_Tcell2_48 "电池单体低温二级报警温度";
CM_ SG_ 2417159792 S2P_Lmt10_Under_DTcell2_48 "单体低温2级告警消除回差阈值";
CM_ SG_ 2417159792 S2P_Lmt10_Under_Tcell3_48 "电池单体低温三级报警温度";
CM_ SG_ 2417159792 S2P_Lmt10_Under_DTcell3_48 "单体低温3级告警消除回差阈值";
CM_ SG_ 2417159793 S2P_Lmt10_Under_Tcell1_49 "电池单体低温一级报警温度";
CM_ SG_ 2417159793 S2P_Lmt10_Under_DTcell1_49 "单体低温1级告警消除回差阈值";
CM_ SG_ 2417159793 S2P_Lmt10_Under_Tcell2_49 "电池单体低温二级报警温度";
CM_ SG_ 2417159793 S2P_Lmt10_Under_DTcell2_49 "单体低温2级告警消除回差阈值";
CM_ SG_ 2417159793 S2P_Lmt10_Under_Tcell3_49 "电池单体低温三级报警温度";
CM_ SG_ 2417159793 S2P_Lmt10_Under_DTcell3_49 "单体低温3级告警消除回差阈值";
CM_ SG_ 2417159794 S2P_Lmt10_Under_Tcell1_50 "电池单体低温一级报警温度";
CM_ SG_ 2417159794 S2P_Lmt10_Under_DTcell1_50 "单体低温1级告警消除回差阈值";
CM_ SG_ 2417159794 S2P_Lmt10_Under_Tcell2_50 "电池单体低温二级报警温度";
CM_ SG_ 2417159794 S2P_Lmt10_Under_DTcell2_50 "单体低温2级告警消除回差阈值";
CM_ SG_ 2417159794 S2P_Lmt10_Under_Tcell3_50 "电池单体低温三级报警温度";
CM_ SG_ 2417159794 S2P_Lmt10_Under_DTcell3_50 "单体低温3级告警消除回差阈值";
CM_ SG_ 2417159795 S2P_Lmt10_Under_Tcell1_51 "电池单体低温一级报警温度";
CM_ SG_ 2417159795 S2P_Lmt10_Under_DTcell1_51 "单体低温1级告警消除回差阈值";
CM_ SG_ 2417159795 S2P_Lmt10_Under_Tcell2_51 "电池单体低温二级报警温度";
CM_ SG_ 2417159795 S2P_Lmt10_Under_DTcell2_51 "单体低温2级告警消除回差阈值";
CM_ SG_ 2417159795 S2P_Lmt10_Under_Tcell3_51 "电池单体低温三级报警温度";
CM_ SG_ 2417159795 S2P_Lmt10_Under_DTcell3_51 "单体低温3级告警消除回差阈值";
CM_ SG_ 2417159796 S2P_Lmt10_Under_Tcell1_52 "电池单体低温一级报警温度";
CM_ SG_ 2417159796 S2P_Lmt10_Under_DTcell1_52 "单体低温1级告警消除回差阈值";
CM_ SG_ 2417159796 S2P_Lmt10_Under_Tcell2_52 "电池单体低温二级报警温度";
CM_ SG_ 2417159796 S2P_Lmt10_Under_DTcell2_52 "单体低温2级告警消除回差阈值";
CM_ SG_ 2417159796 S2P_Lmt10_Under_Tcell3_52 "电池单体低温三级报警温度";
CM_ SG_ 2417159796 S2P_Lmt10_Under_DTcell3_52 "单体低温3级告警消除回差阈值";
CM_ SG_ 2417159797 S2P_Lmt10_Under_Tcell1_53 "电池单体低温一级报警温度";
CM_ SG_ 2417159797 S2P_Lmt10_Under_DTcell1_53 "单体低温1级告警消除回差阈值";
CM_ SG_ 2417159797 S2P_Lmt10_Under_Tcell2_53 "电池单体低温二级报警温度";
CM_ SG_ 2417159797 S2P_Lmt10_Under_DTcell2_53 "单体低温2级告警消除回差阈值";
CM_ SG_ 2417159797 S2P_Lmt10_Under_Tcell3_53 "电池单体低温三级报警温度";
CM_ SG_ 2417159797 S2P_Lmt10_Under_DTcell3_53 "单体低温3级告警消除回差阈值";
CM_ SG_ 2417159798 S2P_Lmt10_Under_Tcell1_54 "电池单体低温一级报警温度";
CM_ SG_ 2417159798 S2P_Lmt10_Under_DTcell1_54 "单体低温1级告警消除回差阈值";
CM_ SG_ 2417159798 S2P_Lmt10_Under_Tcell2_54 "电池单体低温二级报警温度";
CM_ SG_ 2417159798 S2P_Lmt10_Under_DTcell2_54 "单体低温2级告警消除回差阈值";
CM_ SG_ 2417159798 S2P_Lmt10_Under_Tcell3_54 "电池单体低温三级报警温度";
CM_ SG_ 2417159798 S2P_Lmt10_Under_DTcell3_54 "单体低温3级告警消除回差阈值";
CM_ SG_ 2417159799 S2P_Lmt10_Under_Tcell1_55 "电池单体低温一级报警温度";
CM_ SG_ 2417159799 S2P_Lmt10_Under_DTcell1_55 "单体低温1级告警消除回差阈值";
CM_ SG_ 2417159799 S2P_Lmt10_Under_Tcell2_55 "电池单体低温二级报警温度";
CM_ SG_ 2417159799 S2P_Lmt10_Under_DTcell2_55 "单体低温2级告警消除回差阈值";
CM_ SG_ 2417159799 S2P_Lmt10_Under_Tcell3_55 "电池单体低温三级报警温度";
CM_ SG_ 2417159799 S2P_Lmt10_Under_DTcell3_55 "单体低温3级告警消除回差阈值";
CM_ SG_ 2417159800 S2P_Lmt10_Under_Tcell1_56 "电池单体低温一级报警温度";
CM_ SG_ 2417159800 S2P_Lmt10_Under_DTcell1_56 "单体低温1级告警消除回差阈值";
CM_ SG_ 2417159800 S2P_Lmt10_Under_Tcell2_56 "电池单体低温二级报警温度";
CM_ SG_ 2417159800 S2P_Lmt10_Under_DTcell2_56 "单体低温2级告警消除回差阈值";
CM_ SG_ 2417159800 S2P_Lmt10_Under_Tcell3_56 "电池单体低温三级报警温度";
CM_ SG_ 2417159800 S2P_Lmt10_Under_DTcell3_56 "单体低温3级告警消除回差阈值";
CM_ SG_ 2417159801 S2P_Lmt10_Under_Tcell1_57 "电池单体低温一级报警温度";
CM_ SG_ 2417159801 S2P_Lmt10_Under_DTcell1_57 "单体低温1级告警消除回差阈值";
CM_ SG_ 2417159801 S2P_Lmt10_Under_Tcell2_57 "电池单体低温二级报警温度";
CM_ SG_ 2417159801 S2P_Lmt10_Under_DTcell2_57 "单体低温2级告警消除回差阈值";
CM_ SG_ 2417159801 S2P_Lmt10_Under_Tcell3_57 "电池单体低温三级报警温度";
CM_ SG_ 2417159801 S2P_Lmt10_Under_DTcell3_57 "单体低温3级告警消除回差阈值";
CM_ SG_ 2417159802 S2P_Lmt10_Under_Tcell1_58 "电池单体低温一级报警温度";
CM_ SG_ 2417159802 S2P_Lmt10_Under_DTcell1_58 "单体低温1级告警消除回差阈值";
CM_ SG_ 2417159802 S2P_Lmt10_Under_Tcell2_58 "电池单体低温二级报警温度";
CM_ SG_ 2417159802 S2P_Lmt10_Under_DTcell2_58 "单体低温2级告警消除回差阈值";
CM_ SG_ 2417159802 S2P_Lmt10_Under_Tcell3_58 "电池单体低温三级报警温度";
CM_ SG_ 2417159802 S2P_Lmt10_Under_DTcell3_58 "单体低温3级告警消除回差阈值";
CM_ SG_ 2417159803 S2P_Lmt10_Under_Tcell1_59 "电池单体低温一级报警温度";
CM_ SG_ 2417159803 S2P_Lmt10_Under_DTcell1_59 "单体低温1级告警消除回差阈值";
CM_ SG_ 2417159803 S2P_Lmt10_Under_Tcell2_59 "电池单体低温二级报警温度";
CM_ SG_ 2417159803 S2P_Lmt10_Under_DTcell2_59 "单体低温2级告警消除回差阈值";
CM_ SG_ 2417159803 S2P_Lmt10_Under_Tcell3_59 "电池单体低温三级报警温度";
CM_ SG_ 2417159803 S2P_Lmt10_Under_DTcell3_59 "单体低温3级告警消除回差阈值";
CM_ SG_ 2417159804 S2P_Lmt10_Under_Tcell1_60 "电池单体低温一级报警温度";
CM_ SG_ 2417159804 S2P_Lmt10_Under_DTcell1_60 "单体低温1级告警消除回差阈值";
CM_ SG_ 2417159804 S2P_Lmt10_Under_Tcell2_60 "电池单体低温二级报警温度";
CM_ SG_ 2417159804 S2P_Lmt10_Under_DTcell2_60 "单体低温2级告警消除回差阈值";
CM_ SG_ 2417159804 S2P_Lmt10_Under_Tcell3_60 "电池单体低温三级报警温度";
CM_ SG_ 2417159804 S2P_Lmt10_Under_DTcell3_60 "单体低温3级告警消除回差阈值";
CM_ SG_ 2417159805 S2P_Lmt10_Under_Tcell1_61 "电池单体低温一级报警温度";
CM_ SG_ 2417159805 S2P_Lmt10_Under_DTcell1_61 "单体低温1级告警消除回差阈值";
CM_ SG_ 2417159805 S2P_Lmt10_Under_Tcell2_61 "电池单体低温二级报警温度";
CM_ SG_ 2417159805 S2P_Lmt10_Under_DTcell2_61 "单体低温2级告警消除回差阈值";
CM_ SG_ 2417159805 S2P_Lmt10_Under_Tcell3_61 "电池单体低温三级报警温度";
CM_ SG_ 2417159805 S2P_Lmt10_Under_DTcell3_61 "单体低温3级告警消除回差阈值";
CM_ SG_ 2417159806 S2P_Lmt10_Under_Tcell1_62 "电池单体低温一级报警温度";
CM_ SG_ 2417159806 S2P_Lmt10_Under_DTcell1_62 "单体低温1级告警消除回差阈值";
CM_ SG_ 2417159806 S2P_Lmt10_Under_Tcell2_62 "电池单体低温二级报警温度";
CM_ SG_ 2417159806 S2P_Lmt10_Under_DTcell2_62 "单体低温2级告警消除回差阈值";
CM_ SG_ 2417159806 S2P_Lmt10_Under_Tcell3_62 "电池单体低温三级报警温度";
CM_ SG_ 2417159806 S2P_Lmt10_Under_DTcell3_62 "单体低温3级告警消除回差阈值";
CM_ SG_ 2417159807 S2P_Lmt10_Under_Tcell1_63 "电池单体低温一级报警温度";
CM_ SG_ 2417159807 S2P_Lmt10_Under_DTcell1_63 "单体低温1级告警消除回差阈值";
CM_ SG_ 2417159807 S2P_Lmt10_Under_Tcell2_63 "电池单体低温二级报警温度";
CM_ SG_ 2417159807 S2P_Lmt10_Under_DTcell2_63 "单体低温2级告警消除回差阈值";
CM_ SG_ 2417159807 S2P_Lmt10_Under_Tcell3_63 "电池单体低温三级报警温度";
CM_ SG_ 2417159807 S2P_Lmt10_Under_DTcell3_63 "单体低温3级告警消除回差阈值";
CM_ SG_ 2417225281 S2P_Lmt11_Over_DeltTcell1_01 "电池温差过大1级告警阈值";
CM_ SG_ 2417225281 S2P_Lmt11_Over_DeltTcell2_01 "电池温差过大2级告警阈值";
CM_ SG_ 2417225281 S2P_Lmt11_Over_DeltTcell3_01 "电池温差过大3级告警阈值";
CM_ SG_ 2417225281 S2P_Lmt11_Over_DDeltTcell_01 "电池温差过大告警消除回差阈值";
CM_ SG_ 2417225281 S2P_Lmt11_Over_Utank4_01 "电池簇充电截止电压";
CM_ SG_ 2417225281 S2P_Lmt11_Under_Utank4_01 "电池簇放电截止电压";
CM_ SG_ 2417225282 S2P_Lmt11_Over_DeltTcell1_02 "电池温差过大1级告警阈值";
CM_ SG_ 2417225282 S2P_Lmt11_Over_DeltTcell2_02 "电池温差过大2级告警阈值";
CM_ SG_ 2417225282 S2P_Lmt11_Over_DeltTcell3_02 "电池温差过大3级告警阈值";
CM_ SG_ 2417225282 S2P_Lmt11_Over_DDeltTcell_02 "电池温差过大告警消除回差阈值";
CM_ SG_ 2417225282 S2P_Lmt11_Over_Utank4_02 "电池簇充电截止电压";
CM_ SG_ 2417225282 S2P_Lmt11_Under_Utank4_02 "电池簇放电截止电压";
CM_ SG_ 2417225283 S2P_Lmt11_Over_DeltTcell1_03 "电池温差过大1级告警阈值";
CM_ SG_ 2417225283 S2P_Lmt11_Over_DeltTcell2_03 "电池温差过大2级告警阈值";
CM_ SG_ 2417225283 S2P_Lmt11_Over_DeltTcell3_03 "电池温差过大3级告警阈值";
CM_ SG_ 2417225283 S2P_Lmt11_Over_DDeltTcell_03 "电池温差过大告警消除回差阈值";
CM_ SG_ 2417225283 S2P_Lmt11_Over_Utank4_03 "电池簇充电截止电压";
CM_ SG_ 2417225283 S2P_Lmt11_Under_Utank4_03 "电池簇放电截止电压";
CM_ SG_ 2417225284 S2P_Lmt11_Over_DeltTcell1_04 "电池温差过大1级告警阈值";
CM_ SG_ 2417225284 S2P_Lmt11_Over_DeltTcell2_04 "电池温差过大2级告警阈值";
CM_ SG_ 2417225284 S2P_Lmt11_Over_DeltTcell3_04 "电池温差过大3级告警阈值";
CM_ SG_ 2417225284 S2P_Lmt11_Over_DDeltTcell_04 "电池温差过大告警消除回差阈值";
CM_ SG_ 2417225284 S2P_Lmt11_Over_Utank4_04 "电池簇充电截止电压";
CM_ SG_ 2417225284 S2P_Lmt11_Under_Utank4_04 "电池簇放电截止电压";
CM_ SG_ 2417225285 S2P_Lmt11_Over_DeltTcell1_05 "电池温差过大1级告警阈值";
CM_ SG_ 2417225285 S2P_Lmt11_Over_DeltTcell2_05 "电池温差过大2级告警阈值";
CM_ SG_ 2417225285 S2P_Lmt11_Over_DeltTcell3_05 "电池温差过大3级告警阈值";
CM_ SG_ 2417225285 S2P_Lmt11_Over_DDeltTcell_05 "电池温差过大告警消除回差阈值";
CM_ SG_ 2417225285 S2P_Lmt11_Over_Utank4_05 "电池簇充电截止电压";
CM_ SG_ 2417225285 S2P_Lmt11_Under_Utank4_05 "电池簇放电截止电压";
CM_ SG_ 2417225286 S2P_Lmt11_Over_DeltTcell1_06 "电池温差过大1级告警阈值";
CM_ SG_ 2417225286 S2P_Lmt11_Over_DeltTcell2_06 "电池温差过大2级告警阈值";
CM_ SG_ 2417225286 S2P_Lmt11_Over_DeltTcell3_06 "电池温差过大3级告警阈值";
CM_ SG_ 2417225286 S2P_Lmt11_Over_DDeltTcell_06 "电池温差过大告警消除回差阈值";
CM_ SG_ 2417225286 S2P_Lmt11_Over_Utank4_06 "电池簇充电截止电压";
CM_ SG_ 2417225286 S2P_Lmt11_Under_Utank4_06 "电池簇放电截止电压";
CM_ SG_ 2417225287 S2P_Lmt11_Over_DeltTcell1_07 "电池温差过大1级告警阈值";
CM_ SG_ 2417225287 S2P_Lmt11_Over_DeltTcell2_07 "电池温差过大2级告警阈值";
CM_ SG_ 2417225287 S2P_Lmt11_Over_DeltTcell3_07 "电池温差过大3级告警阈值";
CM_ SG_ 2417225287 S2P_Lmt11_Over_DDeltTcell_07 "电池温差过大告警消除回差阈值";
CM_ SG_ 2417225287 S2P_Lmt11_Over_Utank4_07 "电池簇充电截止电压";
CM_ SG_ 2417225287 S2P_Lmt11_Under_Utank4_07 "电池簇放电截止电压";
CM_ SG_ 2417225288 S2P_Lmt11_Over_DeltTcell1_08 "电池温差过大1级告警阈值";
CM_ SG_ 2417225288 S2P_Lmt11_Over_DeltTcell2_08 "电池温差过大2级告警阈值";
CM_ SG_ 2417225288 S2P_Lmt11_Over_DeltTcell3_08 "电池温差过大3级告警阈值";
CM_ SG_ 2417225288 S2P_Lmt11_Over_DDeltTcell_08 "电池温差过大告警消除回差阈值";
CM_ SG_ 2417225288 S2P_Lmt11_Over_Utank4_08 "电池簇充电截止电压";
CM_ SG_ 2417225288 S2P_Lmt11_Under_Utank4_08 "电池簇放电截止电压";
CM_ SG_ 2417225289 S2P_Lmt11_Over_DeltTcell1_09 "电池温差过大1级告警阈值";
CM_ SG_ 2417225289 S2P_Lmt11_Over_DeltTcell2_09 "电池温差过大2级告警阈值";
CM_ SG_ 2417225289 S2P_Lmt11_Over_DeltTcell3_09 "电池温差过大3级告警阈值";
CM_ SG_ 2417225289 S2P_Lmt11_Over_DDeltTcell_09 "电池温差过大告警消除回差阈值";
CM_ SG_ 2417225289 S2P_Lmt11_Over_Utank4_09 "电池簇充电截止电压";
CM_ SG_ 2417225289 S2P_Lmt11_Under_Utank4_09 "电池簇放电截止电压";
CM_ SG_ 2417225290 S2P_Lmt11_Over_DeltTcell1_10 "电池温差过大1级告警阈值";
CM_ SG_ 2417225290 S2P_Lmt11_Over_DeltTcell2_10 "电池温差过大2级告警阈值";
CM_ SG_ 2417225290 S2P_Lmt11_Over_DeltTcell3_10 "电池温差过大3级告警阈值";
CM_ SG_ 2417225290 S2P_Lmt11_Over_DDeltTcell_10 "电池温差过大告警消除回差阈值";
CM_ SG_ 2417225290 S2P_Lmt11_Over_Utank4_10 "电池簇充电截止电压";
CM_ SG_ 2417225290 S2P_Lmt11_Under_Utank4_10 "电池簇放电截止电压";
CM_ SG_ 2417225291 S2P_Lmt11_Over_DeltTcell1_11 "电池温差过大1级告警阈值";
CM_ SG_ 2417225291 S2P_Lmt11_Over_DeltTcell2_11 "电池温差过大2级告警阈值";
CM_ SG_ 2417225291 S2P_Lmt11_Over_DeltTcell3_11 "电池温差过大3级告警阈值";
CM_ SG_ 2417225291 S2P_Lmt11_Over_DDeltTcell_11 "电池温差过大告警消除回差阈值";
CM_ SG_ 2417225291 S2P_Lmt11_Over_Utank4_11 "电池簇充电截止电压";
CM_ SG_ 2417225291 S2P_Lmt11_Under_Utank4_11 "电池簇放电截止电压";
CM_ SG_ 2417225292 S2P_Lmt11_Over_DeltTcell1_12 "电池温差过大1级告警阈值";
CM_ SG_ 2417225292 S2P_Lmt11_Over_DeltTcell2_12 "电池温差过大2级告警阈值";
CM_ SG_ 2417225292 S2P_Lmt11_Over_DeltTcell3_12 "电池温差过大3级告警阈值";
CM_ SG_ 2417225292 S2P_Lmt11_Over_DDeltTcell_12 "电池温差过大告警消除回差阈值";
CM_ SG_ 2417225292 S2P_Lmt11_Over_Utank4_12 "电池簇充电截止电压";
CM_ SG_ 2417225292 S2P_Lmt11_Under_Utank4_12 "电池簇放电截止电压";
CM_ SG_ 2417225293 S2P_Lmt11_Over_DeltTcell1_13 "电池温差过大1级告警阈值";
CM_ SG_ 2417225293 S2P_Lmt11_Over_DeltTcell2_13 "电池温差过大2级告警阈值";
CM_ SG_ 2417225293 S2P_Lmt11_Over_DeltTcell3_13 "电池温差过大3级告警阈值";
CM_ SG_ 2417225293 S2P_Lmt11_Over_DDeltTcell_13 "电池温差过大告警消除回差阈值";
CM_ SG_ 2417225293 S2P_Lmt11_Over_Utank4_13 "电池簇充电截止电压";
CM_ SG_ 2417225293 S2P_Lmt11_Under_Utank4_13 "电池簇放电截止电压";
CM_ SG_ 2417225294 S2P_Lmt11_Over_DeltTcell1_14 "电池温差过大1级告警阈值";
CM_ SG_ 2417225294 S2P_Lmt11_Over_DeltTcell2_14 "电池温差过大2级告警阈值";
CM_ SG_ 2417225294 S2P_Lmt11_Over_DeltTcell3_14 "电池温差过大3级告警阈值";
CM_ SG_ 2417225294 S2P_Lmt11_Over_DDeltTcell_14 "电池温差过大告警消除回差阈值";
CM_ SG_ 2417225294 S2P_Lmt11_Over_Utank4_14 "电池簇充电截止电压";
CM_ SG_ 2417225294 S2P_Lmt11_Under_Utank4_14 "电池簇放电截止电压";
CM_ SG_ 2417225295 S2P_Lmt11_Over_DeltTcell1_15 "电池温差过大1级告警阈值";
CM_ SG_ 2417225295 S2P_Lmt11_Over_DeltTcell2_15 "电池温差过大2级告警阈值";
CM_ SG_ 2417225295 S2P_Lmt11_Over_DeltTcell3_15 "电池温差过大3级告警阈值";
CM_ SG_ 2417225295 S2P_Lmt11_Over_DDeltTcell_15 "电池温差过大告警消除回差阈值";
CM_ SG_ 2417225295 S2P_Lmt11_Over_Utank4_15 "电池簇充电截止电压";
CM_ SG_ 2417225295 S2P_Lmt11_Under_Utank4_15 "电池簇放电截止电压";
CM_ SG_ 2417225296 S2P_Lmt11_Over_DeltTcell1_16 "电池温差过大1级告警阈值";
CM_ SG_ 2417225296 S2P_Lmt11_Over_DeltTcell2_16 "电池温差过大2级告警阈值";
CM_ SG_ 2417225296 S2P_Lmt11_Over_DeltTcell3_16 "电池温差过大3级告警阈值";
CM_ SG_ 2417225296 S2P_Lmt11_Over_DDeltTcell_16 "电池温差过大告警消除回差阈值";
CM_ SG_ 2417225296 S2P_Lmt11_Over_Utank4_16 "电池簇充电截止电压";
CM_ SG_ 2417225296 S2P_Lmt11_Under_Utank4_16 "电池簇放电截止电压";
CM_ SG_ 2417225297 S2P_Lmt11_Over_DeltTcell1_17 "电池温差过大1级告警阈值";
CM_ SG_ 2417225297 S2P_Lmt11_Over_DeltTcell2_17 "电池温差过大2级告警阈值";
CM_ SG_ 2417225297 S2P_Lmt11_Over_DeltTcell3_17 "电池温差过大3级告警阈值";
CM_ SG_ 2417225297 S2P_Lmt11_Over_DDeltTcell_17 "电池温差过大告警消除回差阈值";
CM_ SG_ 2417225297 S2P_Lmt11_Over_Utank4_17 "电池簇充电截止电压";
CM_ SG_ 2417225297 S2P_Lmt11_Under_Utank4_17 "电池簇放电截止电压";
CM_ SG_ 2417225298 S2P_Lmt11_Over_DeltTcell1_18 "电池温差过大1级告警阈值";
CM_ SG_ 2417225298 S2P_Lmt11_Over_DeltTcell2_18 "电池温差过大2级告警阈值";
CM_ SG_ 2417225298 S2P_Lmt11_Over_DeltTcell3_18 "电池温差过大3级告警阈值";
CM_ SG_ 2417225298 S2P_Lmt11_Over_DDeltTcell_18 "电池温差过大告警消除回差阈值";
CM_ SG_ 2417225298 S2P_Lmt11_Over_Utank4_18 "电池簇充电截止电压";
CM_ SG_ 2417225298 S2P_Lmt11_Under_Utank4_18 "电池簇放电截止电压";
CM_ SG_ 2417225299 S2P_Lmt11_Over_DeltTcell1_19 "电池温差过大1级告警阈值";
CM_ SG_ 2417225299 S2P_Lmt11_Over_DeltTcell2_19 "电池温差过大2级告警阈值";
CM_ SG_ 2417225299 S2P_Lmt11_Over_DeltTcell3_19 "电池温差过大3级告警阈值";
CM_ SG_ 2417225299 S2P_Lmt11_Over_DDeltTcell_19 "电池温差过大告警消除回差阈值";
CM_ SG_ 2417225299 S2P_Lmt11_Over_Utank4_19 "电池簇充电截止电压";
CM_ SG_ 2417225299 S2P_Lmt11_Under_Utank4_19 "电池簇放电截止电压";
CM_ SG_ 2417225300 S2P_Lmt11_Over_DeltTcell1_20 "电池温差过大1级告警阈值";
CM_ SG_ 2417225300 S2P_Lmt11_Over_DeltTcell2_20 "电池温差过大2级告警阈值";
CM_ SG_ 2417225300 S2P_Lmt11_Over_DeltTcell3_20 "电池温差过大3级告警阈值";
CM_ SG_ 2417225300 S2P_Lmt11_Over_DDeltTcell_20 "电池温差过大告警消除回差阈值";
CM_ SG_ 2417225300 S2P_Lmt11_Over_Utank4_20 "电池簇充电截止电压";
CM_ SG_ 2417225300 S2P_Lmt11_Under_Utank4_20 "电池簇放电截止电压";
CM_ SG_ 2417225301 S2P_Lmt11_Over_DeltTcell1_21 "电池温差过大1级告警阈值";
CM_ SG_ 2417225301 S2P_Lmt11_Over_DeltTcell2_21 "电池温差过大2级告警阈值";
CM_ SG_ 2417225301 S2P_Lmt11_Over_DeltTcell3_21 "电池温差过大3级告警阈值";
CM_ SG_ 2417225301 S2P_Lmt11_Over_DDeltTcell_21 "电池温差过大告警消除回差阈值";
CM_ SG_ 2417225301 S2P_Lmt11_Over_Utank4_21 "电池簇充电截止电压";
CM_ SG_ 2417225301 S2P_Lmt11_Under_Utank4_21 "电池簇放电截止电压";
CM_ SG_ 2417225302 S2P_Lmt11_Over_DeltTcell1_22 "电池温差过大1级告警阈值";
CM_ SG_ 2417225302 S2P_Lmt11_Over_DeltTcell2_22 "电池温差过大2级告警阈值";
CM_ SG_ 2417225302 S2P_Lmt11_Over_DeltTcell3_22 "电池温差过大3级告警阈值";
CM_ SG_ 2417225302 S2P_Lmt11_Over_DDeltTcell_22 "电池温差过大告警消除回差阈值";
CM_ SG_ 2417225302 S2P_Lmt11_Over_Utank4_22 "电池簇充电截止电压";
CM_ SG_ 2417225302 S2P_Lmt11_Under_Utank4_22 "电池簇放电截止电压";
CM_ SG_ 2417225303 S2P_Lmt11_Over_DeltTcell1_23 "电池温差过大1级告警阈值";
CM_ SG_ 2417225303 S2P_Lmt11_Over_DeltTcell2_23 "电池温差过大2级告警阈值";
CM_ SG_ 2417225303 S2P_Lmt11_Over_DeltTcell3_23 "电池温差过大3级告警阈值";
CM_ SG_ 2417225303 S2P_Lmt11_Over_DDeltTcell_23 "电池温差过大告警消除回差阈值";
CM_ SG_ 2417225303 S2P_Lmt11_Over_Utank4_23 "电池簇充电截止电压";
CM_ SG_ 2417225303 S2P_Lmt11_Under_Utank4_23 "电池簇放电截止电压";
CM_ SG_ 2417225304 S2P_Lmt11_Over_DeltTcell1_24 "电池温差过大1级告警阈值";
CM_ SG_ 2417225304 S2P_Lmt11_Over_DeltTcell2_24 "电池温差过大2级告警阈值";
CM_ SG_ 2417225304 S2P_Lmt11_Over_DeltTcell3_24 "电池温差过大3级告警阈值";
CM_ SG_ 2417225304 S2P_Lmt11_Over_DDeltTcell_24 "电池温差过大告警消除回差阈值";
CM_ SG_ 2417225304 S2P_Lmt11_Over_Utank4_24 "电池簇充电截止电压";
CM_ SG_ 2417225304 S2P_Lmt11_Under_Utank4_24 "电池簇放电截止电压";
CM_ SG_ 2417225305 S2P_Lmt11_Over_DeltTcell1_25 "电池温差过大1级告警阈值";
CM_ SG_ 2417225305 S2P_Lmt11_Over_DeltTcell2_25 "电池温差过大2级告警阈值";
CM_ SG_ 2417225305 S2P_Lmt11_Over_DeltTcell3_25 "电池温差过大3级告警阈值";
CM_ SG_ 2417225305 S2P_Lmt11_Over_DDeltTcell_25 "电池温差过大告警消除回差阈值";
CM_ SG_ 2417225305 S2P_Lmt11_Over_Utank4_25 "电池簇充电截止电压";
CM_ SG_ 2417225305 S2P_Lmt11_Under_Utank4_25 "电池簇放电截止电压";
CM_ SG_ 2417225306 S2P_Lmt11_Over_DeltTcell1_26 "电池温差过大1级告警阈值";
CM_ SG_ 2417225306 S2P_Lmt11_Over_DeltTcell2_26 "电池温差过大2级告警阈值";
CM_ SG_ 2417225306 S2P_Lmt11_Over_DeltTcell3_26 "电池温差过大3级告警阈值";
CM_ SG_ 2417225306 S2P_Lmt11_Over_DDeltTcell_26 "电池温差过大告警消除回差阈值";
CM_ SG_ 2417225306 S2P_Lmt11_Over_Utank4_26 "电池簇充电截止电压";
CM_ SG_ 2417225306 S2P_Lmt11_Under_Utank4_26 "电池簇放电截止电压";
CM_ SG_ 2417225307 S2P_Lmt11_Over_DeltTcell1_27 "电池温差过大1级告警阈值";
CM_ SG_ 2417225307 S2P_Lmt11_Over_DeltTcell2_27 "电池温差过大2级告警阈值";
CM_ SG_ 2417225307 S2P_Lmt11_Over_DeltTcell3_27 "电池温差过大3级告警阈值";
CM_ SG_ 2417225307 S2P_Lmt11_Over_DDeltTcell_27 "电池温差过大告警消除回差阈值";
CM_ SG_ 2417225307 S2P_Lmt11_Over_Utank4_27 "电池簇充电截止电压";
CM_ SG_ 2417225307 S2P_Lmt11_Under_Utank4_27 "电池簇放电截止电压";
CM_ SG_ 2417225308 S2P_Lmt11_Over_DeltTcell1_28 "电池温差过大1级告警阈值";
CM_ SG_ 2417225308 S2P_Lmt11_Over_DeltTcell2_28 "电池温差过大2级告警阈值";
CM_ SG_ 2417225308 S2P_Lmt11_Over_DeltTcell3_28 "电池温差过大3级告警阈值";
CM_ SG_ 2417225308 S2P_Lmt11_Over_DDeltTcell_28 "电池温差过大告警消除回差阈值";
CM_ SG_ 2417225308 S2P_Lmt11_Over_Utank4_28 "电池簇充电截止电压";
CM_ SG_ 2417225308 S2P_Lmt11_Under_Utank4_28 "电池簇放电截止电压";
CM_ SG_ 2417225309 S2P_Lmt11_Over_DeltTcell1_29 "电池温差过大1级告警阈值";
CM_ SG_ 2417225309 S2P_Lmt11_Over_DeltTcell2_29 "电池温差过大2级告警阈值";
CM_ SG_ 2417225309 S2P_Lmt11_Over_DeltTcell3_29 "电池温差过大3级告警阈值";
CM_ SG_ 2417225309 S2P_Lmt11_Over_DDeltTcell_29 "电池温差过大告警消除回差阈值";
CM_ SG_ 2417225309 S2P_Lmt11_Over_Utank4_29 "电池簇充电截止电压";
CM_ SG_ 2417225309 S2P_Lmt11_Under_Utank4_29 "电池簇放电截止电压";
CM_ SG_ 2417225310 S2P_Lmt11_Over_DeltTcell1_30 "电池温差过大1级告警阈值";
CM_ SG_ 2417225310 S2P_Lmt11_Over_DeltTcell2_30 "电池温差过大2级告警阈值";
CM_ SG_ 2417225310 S2P_Lmt11_Over_DeltTcell3_30 "电池温差过大3级告警阈值";
CM_ SG_ 2417225310 S2P_Lmt11_Over_DDeltTcell_30 "电池温差过大告警消除回差阈值";
CM_ SG_ 2417225310 S2P_Lmt11_Over_Utank4_30 "电池簇充电截止电压";
CM_ SG_ 2417225310 S2P_Lmt11_Under_Utank4_30 "电池簇放电截止电压";
CM_ SG_ 2417225311 S2P_Lmt11_Over_DeltTcell1_31 "电池温差过大1级告警阈值";
CM_ SG_ 2417225311 S2P_Lmt11_Over_DeltTcell2_31 "电池温差过大2级告警阈值";
CM_ SG_ 2417225311 S2P_Lmt11_Over_DeltTcell3_31 "电池温差过大3级告警阈值";
CM_ SG_ 2417225311 S2P_Lmt11_Over_DDeltTcell_31 "电池温差过大告警消除回差阈值";
CM_ SG_ 2417225311 S2P_Lmt11_Over_Utank4_31 "电池簇充电截止电压";
CM_ SG_ 2417225311 S2P_Lmt11_Under_Utank4_31 "电池簇放电截止电压";
CM_ SG_ 2417225312 S2P_Lmt11_Over_DeltTcell1_32 "电池温差过大1级告警阈值";
CM_ SG_ 2417225312 S2P_Lmt11_Over_DeltTcell2_32 "电池温差过大2级告警阈值";
CM_ SG_ 2417225312 S2P_Lmt11_Over_DeltTcell3_32 "电池温差过大3级告警阈值";
CM_ SG_ 2417225312 S2P_Lmt11_Over_DDeltTcell_32 "电池温差过大告警消除回差阈值";
CM_ SG_ 2417225312 S2P_Lmt11_Over_Utank4_32 "电池簇充电截止电压";
CM_ SG_ 2417225312 S2P_Lmt11_Under_Utank4_32 "电池簇放电截止电压";
CM_ SG_ 2417225313 S2P_Lmt11_Over_DeltTcell1_33 "电池温差过大1级告警阈值";
CM_ SG_ 2417225313 S2P_Lmt11_Over_DeltTcell2_33 "电池温差过大2级告警阈值";
CM_ SG_ 2417225313 S2P_Lmt11_Over_DeltTcell3_33 "电池温差过大3级告警阈值";
CM_ SG_ 2417225313 S2P_Lmt11_Over_DDeltTcell_33 "电池温差过大告警消除回差阈值";
CM_ SG_ 2417225313 S2P_Lmt11_Over_Utank4_33 "电池簇充电截止电压";
CM_ SG_ 2417225313 S2P_Lmt11_Under_Utank4_33 "电池簇放电截止电压";
CM_ SG_ 2417225314 S2P_Lmt11_Over_DeltTcell1_34 "电池温差过大1级告警阈值";
CM_ SG_ 2417225314 S2P_Lmt11_Over_DeltTcell2_34 "电池温差过大2级告警阈值";
CM_ SG_ 2417225314 S2P_Lmt11_Over_DeltTcell3_34 "电池温差过大3级告警阈值";
CM_ SG_ 2417225314 S2P_Lmt11_Over_DDeltTcell_34 "电池温差过大告警消除回差阈值";
CM_ SG_ 2417225314 S2P_Lmt11_Over_Utank4_34 "电池簇充电截止电压";
CM_ SG_ 2417225314 S2P_Lmt11_Under_Utank4_34 "电池簇放电截止电压";
CM_ SG_ 2417225315 S2P_Lmt11_Over_DeltTcell1_35 "电池温差过大1级告警阈值";
CM_ SG_ 2417225315 S2P_Lmt11_Over_DeltTcell2_35 "电池温差过大2级告警阈值";
CM_ SG_ 2417225315 S2P_Lmt11_Over_DeltTcell3_35 "电池温差过大3级告警阈值";
CM_ SG_ 2417225315 S2P_Lmt11_Over_DDeltTcell_35 "电池温差过大告警消除回差阈值";
CM_ SG_ 2417225315 S2P_Lmt11_Over_Utank4_35 "电池簇充电截止电压";
CM_ SG_ 2417225315 S2P_Lmt11_Under_Utank4_35 "电池簇放电截止电压";
CM_ SG_ 2417225316 S2P_Lmt11_Over_DeltTcell1_36 "电池温差过大1级告警阈值";
CM_ SG_ 2417225316 S2P_Lmt11_Over_DeltTcell2_36 "电池温差过大2级告警阈值";
CM_ SG_ 2417225316 S2P_Lmt11_Over_DeltTcell3_36 "电池温差过大3级告警阈值";
CM_ SG_ 2417225316 S2P_Lmt11_Over_DDeltTcell_36 "电池温差过大告警消除回差阈值";
CM_ SG_ 2417225316 S2P_Lmt11_Over_Utank4_36 "电池簇充电截止电压";
CM_ SG_ 2417225316 S2P_Lmt11_Under_Utank4_36 "电池簇放电截止电压";
CM_ SG_ 2417225317 S2P_Lmt11_Over_DeltTcell1_37 "电池温差过大1级告警阈值";
CM_ SG_ 2417225317 S2P_Lmt11_Over_DeltTcell2_37 "电池温差过大2级告警阈值";
CM_ SG_ 2417225317 S2P_Lmt11_Over_DeltTcell3_37 "电池温差过大3级告警阈值";
CM_ SG_ 2417225317 S2P_Lmt11_Over_DDeltTcell_37 "电池温差过大告警消除回差阈值";
CM_ SG_ 2417225317 S2P_Lmt11_Over_Utank4_37 "电池簇充电截止电压";
CM_ SG_ 2417225317 S2P_Lmt11_Under_Utank4_37 "电池簇放电截止电压";
CM_ SG_ 2417225318 S2P_Lmt11_Over_DeltTcell1_38 "电池温差过大1级告警阈值";
CM_ SG_ 2417225318 S2P_Lmt11_Over_DeltTcell2_38 "电池温差过大2级告警阈值";
CM_ SG_ 2417225318 S2P_Lmt11_Over_DeltTcell3_38 "电池温差过大3级告警阈值";
CM_ SG_ 2417225318 S2P_Lmt11_Over_DDeltTcell_38 "电池温差过大告警消除回差阈值";
CM_ SG_ 2417225318 S2P_Lmt11_Over_Utank4_38 "电池簇充电截止电压";
CM_ SG_ 2417225318 S2P_Lmt11_Under_Utank4_38 "电池簇放电截止电压";
CM_ SG_ 2417225319 S2P_Lmt11_Over_DeltTcell1_39 "电池温差过大1级告警阈值";
CM_ SG_ 2417225319 S2P_Lmt11_Over_DeltTcell2_39 "电池温差过大2级告警阈值";
CM_ SG_ 2417225319 S2P_Lmt11_Over_DeltTcell3_39 "电池温差过大3级告警阈值";
CM_ SG_ 2417225319 S2P_Lmt11_Over_DDeltTcell_39 "电池温差过大告警消除回差阈值";
CM_ SG_ 2417225319 S2P_Lmt11_Over_Utank4_39 "电池簇充电截止电压";
CM_ SG_ 2417225319 S2P_Lmt11_Under_Utank4_39 "电池簇放电截止电压";
CM_ SG_ 2417225320 S2P_Lmt11_Over_DeltTcell1_40 "电池温差过大1级告警阈值";
CM_ SG_ 2417225320 S2P_Lmt11_Over_DeltTcell2_40 "电池温差过大2级告警阈值";
CM_ SG_ 2417225320 S2P_Lmt11_Over_DeltTcell3_40 "电池温差过大3级告警阈值";
CM_ SG_ 2417225320 S2P_Lmt11_Over_DDeltTcell_40 "电池温差过大告警消除回差阈值";
CM_ SG_ 2417225320 S2P_Lmt11_Over_Utank4_40 "电池簇充电截止电压";
CM_ SG_ 2417225320 S2P_Lmt11_Under_Utank4_40 "电池簇放电截止电压";
CM_ SG_ 2417225321 S2P_Lmt11_Over_DeltTcell1_41 "电池温差过大1级告警阈值";
CM_ SG_ 2417225321 S2P_Lmt11_Over_DeltTcell2_41 "电池温差过大2级告警阈值";
CM_ SG_ 2417225321 S2P_Lmt11_Over_DeltTcell3_41 "电池温差过大3级告警阈值";
CM_ SG_ 2417225321 S2P_Lmt11_Over_DDeltTcell_41 "电池温差过大告警消除回差阈值";
CM_ SG_ 2417225321 S2P_Lmt11_Over_Utank4_41 "电池簇充电截止电压";
CM_ SG_ 2417225321 S2P_Lmt11_Under_Utank4_41 "电池簇放电截止电压";
CM_ SG_ 2417225322 S2P_Lmt11_Over_DeltTcell1_42 "电池温差过大1级告警阈值";
CM_ SG_ 2417225322 S2P_Lmt11_Over_DeltTcell2_42 "电池温差过大2级告警阈值";
CM_ SG_ 2417225322 S2P_Lmt11_Over_DeltTcell3_42 "电池温差过大3级告警阈值";
CM_ SG_ 2417225322 S2P_Lmt11_Over_DDeltTcell_42 "电池温差过大告警消除回差阈值";
CM_ SG_ 2417225322 S2P_Lmt11_Over_Utank4_42 "电池簇充电截止电压";
CM_ SG_ 2417225322 S2P_Lmt11_Under_Utank4_42 "电池簇放电截止电压";
CM_ SG_ 2417225323 S2P_Lmt11_Over_DeltTcell1_43 "电池温差过大1级告警阈值";
CM_ SG_ 2417225323 S2P_Lmt11_Over_DeltTcell2_43 "电池温差过大2级告警阈值";
CM_ SG_ 2417225323 S2P_Lmt11_Over_DeltTcell3_43 "电池温差过大3级告警阈值";
CM_ SG_ 2417225323 S2P_Lmt11_Over_DDeltTcell_43 "电池温差过大告警消除回差阈值";
CM_ SG_ 2417225323 S2P_Lmt11_Over_Utank4_43 "电池簇充电截止电压";
CM_ SG_ 2417225323 S2P_Lmt11_Under_Utank4_43 "电池簇放电截止电压";
CM_ SG_ 2417225324 S2P_Lmt11_Over_DeltTcell1_44 "电池温差过大1级告警阈值";
CM_ SG_ 2417225324 S2P_Lmt11_Over_DeltTcell2_44 "电池温差过大2级告警阈值";
CM_ SG_ 2417225324 S2P_Lmt11_Over_DeltTcell3_44 "电池温差过大3级告警阈值";
CM_ SG_ 2417225324 S2P_Lmt11_Over_DDeltTcell_44 "电池温差过大告警消除回差阈值";
CM_ SG_ 2417225324 S2P_Lmt11_Over_Utank4_44 "电池簇充电截止电压";
CM_ SG_ 2417225324 S2P_Lmt11_Under_Utank4_44 "电池簇放电截止电压";
CM_ SG_ 2417225325 S2P_Lmt11_Over_DeltTcell1_45 "电池温差过大1级告警阈值";
CM_ SG_ 2417225325 S2P_Lmt11_Over_DeltTcell2_45 "电池温差过大2级告警阈值";
CM_ SG_ 2417225325 S2P_Lmt11_Over_DeltTcell3_45 "电池温差过大3级告警阈值";
CM_ SG_ 2417225325 S2P_Lmt11_Over_DDeltTcell_45 "电池温差过大告警消除回差阈值";
CM_ SG_ 2417225325 S2P_Lmt11_Over_Utank4_45 "电池簇充电截止电压";
CM_ SG_ 2417225325 S2P_Lmt11_Under_Utank4_45 "电池簇放电截止电压";
CM_ SG_ 2417225326 S2P_Lmt11_Over_DeltTcell1_46 "电池温差过大1级告警阈值";
CM_ SG_ 2417225326 S2P_Lmt11_Over_DeltTcell2_46 "电池温差过大2级告警阈值";
CM_ SG_ 2417225326 S2P_Lmt11_Over_DeltTcell3_46 "电池温差过大3级告警阈值";
CM_ SG_ 2417225326 S2P_Lmt11_Over_DDeltTcell_46 "电池温差过大告警消除回差阈值";
CM_ SG_ 2417225326 S2P_Lmt11_Over_Utank4_46 "电池簇充电截止电压";
CM_ SG_ 2417225326 S2P_Lmt11_Under_Utank4_46 "电池簇放电截止电压";
CM_ SG_ 2417225327 S2P_Lmt11_Over_DeltTcell1_47 "电池温差过大1级告警阈值";
CM_ SG_ 2417225327 S2P_Lmt11_Over_DeltTcell2_47 "电池温差过大2级告警阈值";
CM_ SG_ 2417225327 S2P_Lmt11_Over_DeltTcell3_47 "电池温差过大3级告警阈值";
CM_ SG_ 2417225327 S2P_Lmt11_Over_DDeltTcell_47 "电池温差过大告警消除回差阈值";
CM_ SG_ 2417225327 S2P_Lmt11_Over_Utank4_47 "电池簇充电截止电压";
CM_ SG_ 2417225327 S2P_Lmt11_Under_Utank4_47 "电池簇放电截止电压";
CM_ SG_ 2417225328 S2P_Lmt11_Over_DeltTcell1_48 "电池温差过大1级告警阈值";
CM_ SG_ 2417225328 S2P_Lmt11_Over_DeltTcell2_48 "电池温差过大2级告警阈值";
CM_ SG_ 2417225328 S2P_Lmt11_Over_DeltTcell3_48 "电池温差过大3级告警阈值";
CM_ SG_ 2417225328 S2P_Lmt11_Over_DDeltTcell_48 "电池温差过大告警消除回差阈值";
CM_ SG_ 2417225328 S2P_Lmt11_Over_Utank4_48 "电池簇充电截止电压";
CM_ SG_ 2417225328 S2P_Lmt11_Under_Utank4_48 "电池簇放电截止电压";
CM_ SG_ 2417225329 S2P_Lmt11_Over_DeltTcell1_49 "电池温差过大1级告警阈值";
CM_ SG_ 2417225329 S2P_Lmt11_Over_DeltTcell2_49 "电池温差过大2级告警阈值";
CM_ SG_ 2417225329 S2P_Lmt11_Over_DeltTcell3_49 "电池温差过大3级告警阈值";
CM_ SG_ 2417225329 S2P_Lmt11_Over_DDeltTcell_49 "电池温差过大告警消除回差阈值";
CM_ SG_ 2417225329 S2P_Lmt11_Over_Utank4_49 "电池簇充电截止电压";
CM_ SG_ 2417225329 S2P_Lmt11_Under_Utank4_49 "电池簇放电截止电压";
CM_ SG_ 2417225330 S2P_Lmt11_Over_DeltTcell1_50 "电池温差过大1级告警阈值";
CM_ SG_ 2417225330 S2P_Lmt11_Over_DeltTcell2_50 "电池温差过大2级告警阈值";
CM_ SG_ 2417225330 S2P_Lmt11_Over_DeltTcell3_50 "电池温差过大3级告警阈值";
CM_ SG_ 2417225330 S2P_Lmt11_Over_DDeltTcell_50 "电池温差过大告警消除回差阈值";
CM_ SG_ 2417225330 S2P_Lmt11_Over_Utank4_50 "电池簇充电截止电压";
CM_ SG_ 2417225330 S2P_Lmt11_Under_Utank4_50 "电池簇放电截止电压";
CM_ SG_ 2417225331 S2P_Lmt11_Over_DeltTcell1_51 "电池温差过大1级告警阈值";
CM_ SG_ 2417225331 S2P_Lmt11_Over_DeltTcell2_51 "电池温差过大2级告警阈值";
CM_ SG_ 2417225331 S2P_Lmt11_Over_DeltTcell3_51 "电池温差过大3级告警阈值";
CM_ SG_ 2417225331 S2P_Lmt11_Over_DDeltTcell_51 "电池温差过大告警消除回差阈值";
CM_ SG_ 2417225331 S2P_Lmt11_Over_Utank4_51 "电池簇充电截止电压";
CM_ SG_ 2417225331 S2P_Lmt11_Under_Utank4_51 "电池簇放电截止电压";
CM_ SG_ 2417225332 S2P_Lmt11_Over_DeltTcell1_52 "电池温差过大1级告警阈值";
CM_ SG_ 2417225332 S2P_Lmt11_Over_DeltTcell2_52 "电池温差过大2级告警阈值";
CM_ SG_ 2417225332 S2P_Lmt11_Over_DeltTcell3_52 "电池温差过大3级告警阈值";
CM_ SG_ 2417225332 S2P_Lmt11_Over_DDeltTcell_52 "电池温差过大告警消除回差阈值";
CM_ SG_ 2417225332 S2P_Lmt11_Over_Utank4_52 "电池簇充电截止电压";
CM_ SG_ 2417225332 S2P_Lmt11_Under_Utank4_52 "电池簇放电截止电压";
CM_ SG_ 2417225333 S2P_Lmt11_Over_DeltTcell1_53 "电池温差过大1级告警阈值";
CM_ SG_ 2417225333 S2P_Lmt11_Over_DeltTcell2_53 "电池温差过大2级告警阈值";
CM_ SG_ 2417225333 S2P_Lmt11_Over_DeltTcell3_53 "电池温差过大3级告警阈值";
CM_ SG_ 2417225333 S2P_Lmt11_Over_DDeltTcell_53 "电池温差过大告警消除回差阈值";
CM_ SG_ 2417225333 S2P_Lmt11_Over_Utank4_53 "电池簇充电截止电压";
CM_ SG_ 2417225333 S2P_Lmt11_Under_Utank4_53 "电池簇放电截止电压";
CM_ SG_ 2417225334 S2P_Lmt11_Over_DeltTcell1_54 "电池温差过大1级告警阈值";
CM_ SG_ 2417225334 S2P_Lmt11_Over_DeltTcell2_54 "电池温差过大2级告警阈值";
CM_ SG_ 2417225334 S2P_Lmt11_Over_DeltTcell3_54 "电池温差过大3级告警阈值";
CM_ SG_ 2417225334 S2P_Lmt11_Over_DDeltTcell_54 "电池温差过大告警消除回差阈值";
CM_ SG_ 2417225334 S2P_Lmt11_Over_Utank4_54 "电池簇充电截止电压";
CM_ SG_ 2417225334 S2P_Lmt11_Under_Utank4_54 "电池簇放电截止电压";
CM_ SG_ 2417225335 S2P_Lmt11_Over_DeltTcell1_55 "电池温差过大1级告警阈值";
CM_ SG_ 2417225335 S2P_Lmt11_Over_DeltTcell2_55 "电池温差过大2级告警阈值";
CM_ SG_ 2417225335 S2P_Lmt11_Over_DeltTcell3_55 "电池温差过大3级告警阈值";
CM_ SG_ 2417225335 S2P_Lmt11_Over_DDeltTcell_55 "电池温差过大告警消除回差阈值";
CM_ SG_ 2417225335 S2P_Lmt11_Over_Utank4_55 "电池簇充电截止电压";
CM_ SG_ 2417225335 S2P_Lmt11_Under_Utank4_55 "电池簇放电截止电压";
CM_ SG_ 2417225336 S2P_Lmt11_Over_DeltTcell1_56 "电池温差过大1级告警阈值";
CM_ SG_ 2417225336 S2P_Lmt11_Over_DeltTcell2_56 "电池温差过大2级告警阈值";
CM_ SG_ 2417225336 S2P_Lmt11_Over_DeltTcell3_56 "电池温差过大3级告警阈值";
CM_ SG_ 2417225336 S2P_Lmt11_Over_DDeltTcell_56 "电池温差过大告警消除回差阈值";
CM_ SG_ 2417225336 S2P_Lmt11_Over_Utank4_56 "电池簇充电截止电压";
CM_ SG_ 2417225336 S2P_Lmt11_Under_Utank4_56 "电池簇放电截止电压";
CM_ SG_ 2417225337 S2P_Lmt11_Over_DeltTcell1_57 "电池温差过大1级告警阈值";
CM_ SG_ 2417225337 S2P_Lmt11_Over_DeltTcell2_57 "电池温差过大2级告警阈值";
CM_ SG_ 2417225337 S2P_Lmt11_Over_DeltTcell3_57 "电池温差过大3级告警阈值";
CM_ SG_ 2417225337 S2P_Lmt11_Over_DDeltTcell_57 "电池温差过大告警消除回差阈值";
CM_ SG_ 2417225337 S2P_Lmt11_Over_Utank4_57 "电池簇充电截止电压";
CM_ SG_ 2417225337 S2P_Lmt11_Under_Utank4_57 "电池簇放电截止电压";
CM_ SG_ 2417225338 S2P_Lmt11_Over_DeltTcell1_58 "电池温差过大1级告警阈值";
CM_ SG_ 2417225338 S2P_Lmt11_Over_DeltTcell2_58 "电池温差过大2级告警阈值";
CM_ SG_ 2417225338 S2P_Lmt11_Over_DeltTcell3_58 "电池温差过大3级告警阈值";
CM_ SG_ 2417225338 S2P_Lmt11_Over_DDeltTcell_58 "电池温差过大告警消除回差阈值";
CM_ SG_ 2417225338 S2P_Lmt11_Over_Utank4_58 "电池簇充电截止电压";
CM_ SG_ 2417225338 S2P_Lmt11_Under_Utank4_58 "电池簇放电截止电压";
CM_ SG_ 2417225339 S2P_Lmt11_Over_DeltTcell1_59 "电池温差过大1级告警阈值";
CM_ SG_ 2417225339 S2P_Lmt11_Over_DeltTcell2_59 "电池温差过大2级告警阈值";
CM_ SG_ 2417225339 S2P_Lmt11_Over_DeltTcell3_59 "电池温差过大3级告警阈值";
CM_ SG_ 2417225339 S2P_Lmt11_Over_DDeltTcell_59 "电池温差过大告警消除回差阈值";
CM_ SG_ 2417225339 S2P_Lmt11_Over_Utank4_59 "电池簇充电截止电压";
CM_ SG_ 2417225339 S2P_Lmt11_Under_Utank4_59 "电池簇放电截止电压";
CM_ SG_ 2417225340 S2P_Lmt11_Over_DeltTcell1_60 "电池温差过大1级告警阈值";
CM_ SG_ 2417225340 S2P_Lmt11_Over_DeltTcell2_60 "电池温差过大2级告警阈值";
CM_ SG_ 2417225340 S2P_Lmt11_Over_DeltTcell3_60 "电池温差过大3级告警阈值";
CM_ SG_ 2417225340 S2P_Lmt11_Over_DDeltTcell_60 "电池温差过大告警消除回差阈值";
CM_ SG_ 2417225340 S2P_Lmt11_Over_Utank4_60 "电池簇充电截止电压";
CM_ SG_ 2417225340 S2P_Lmt11_Under_Utank4_60 "电池簇放电截止电压";
CM_ SG_ 2417225341 S2P_Lmt11_Over_DeltTcell1_61 "电池温差过大1级告警阈值";
CM_ SG_ 2417225341 S2P_Lmt11_Over_DeltTcell2_61 "电池温差过大2级告警阈值";
CM_ SG_ 2417225341 S2P_Lmt11_Over_DeltTcell3_61 "电池温差过大3级告警阈值";
CM_ SG_ 2417225341 S2P_Lmt11_Over_DDeltTcell_61 "电池温差过大告警消除回差阈值";
CM_ SG_ 2417225341 S2P_Lmt11_Over_Utank4_61 "电池簇充电截止电压";
CM_ SG_ 2417225341 S2P_Lmt11_Under_Utank4_61 "电池簇放电截止电压";
CM_ SG_ 2417225342 S2P_Lmt11_Over_DeltTcell1_62 "电池温差过大1级告警阈值";
CM_ SG_ 2417225342 S2P_Lmt11_Over_DeltTcell2_62 "电池温差过大2级告警阈值";
CM_ SG_ 2417225342 S2P_Lmt11_Over_DeltTcell3_62 "电池温差过大3级告警阈值";
CM_ SG_ 2417225342 S2P_Lmt11_Over_DDeltTcell_62 "电池温差过大告警消除回差阈值";
CM_ SG_ 2417225342 S2P_Lmt11_Over_Utank4_62 "电池簇充电截止电压";
CM_ SG_ 2417225342 S2P_Lmt11_Under_Utank4_62 "电池簇放电截止电压";
CM_ SG_ 2417225343 S2P_Lmt11_Over_DeltTcell1_63 "电池温差过大1级告警阈值";
CM_ SG_ 2417225343 S2P_Lmt11_Over_DeltTcell2_63 "电池温差过大2级告警阈值";
CM_ SG_ 2417225343 S2P_Lmt11_Over_DeltTcell3_63 "电池温差过大3级告警阈值";
CM_ SG_ 2417225343 S2P_Lmt11_Over_DDeltTcell_63 "电池温差过大告警消除回差阈值";
CM_ SG_ 2417225343 S2P_Lmt11_Over_Utank4_63 "电池簇充电截止电压";
CM_ SG_ 2417225343 S2P_Lmt11_Under_Utank4_63 "电池簇放电截止电压";
CM_ SG_ 2417290817 S2P_Lmt12_Over_Icharge1_01 "电池簇充电电流一级报警值";
CM_ SG_ 2417290817 S2P_Lmt12_Over_Icharge2_01 "电池簇充电电流二级报警值";
CM_ SG_ 2417290817 S2P_Lmt12_Over_Icharge3_01 "电池簇充电电流三级报警值";
CM_ SG_ 2417290817 S2P_Lmt12_Over_Icharge4_01 "电池簇充电电流截止值";
CM_ SG_ 2417290818 S2P_Lmt12_Over_Icharge1_02 "电池簇充电电流一级报警值";
CM_ SG_ 2417290818 S2P_Lmt12_Over_Icharge2_02 "电池簇充电电流二级报警值";
CM_ SG_ 2417290818 S2P_Lmt12_Over_Icharge3_02 "电池簇充电电流三级报警值";
CM_ SG_ 2417290818 S2P_Lmt12_Over_Icharge4_02 "电池簇充电电流截止值";
CM_ SG_ 2417290819 S2P_Lmt12_Over_Icharge1_03 "电池簇充电电流一级报警值";
CM_ SG_ 2417290819 S2P_Lmt12_Over_Icharge2_03 "电池簇充电电流二级报警值";
CM_ SG_ 2417290819 S2P_Lmt12_Over_Icharge3_03 "电池簇充电电流三级报警值";
CM_ SG_ 2417290819 S2P_Lmt12_Over_Icharge4_03 "电池簇充电电流截止值";
CM_ SG_ 2417290820 S2P_Lmt12_Over_Icharge1_04 "电池簇充电电流一级报警值";
CM_ SG_ 2417290820 S2P_Lmt12_Over_Icharge2_04 "电池簇充电电流二级报警值";
CM_ SG_ 2417290820 S2P_Lmt12_Over_Icharge3_04 "电池簇充电电流三级报警值";
CM_ SG_ 2417290820 S2P_Lmt12_Over_Icharge4_04 "电池簇充电电流截止值";
CM_ SG_ 2417290821 S2P_Lmt12_Over_Icharge1_05 "电池簇充电电流一级报警值";
CM_ SG_ 2417290821 S2P_Lmt12_Over_Icharge2_05 "电池簇充电电流二级报警值";
CM_ SG_ 2417290821 S2P_Lmt12_Over_Icharge3_05 "电池簇充电电流三级报警值";
CM_ SG_ 2417290821 S2P_Lmt12_Over_Icharge4_05 "电池簇充电电流截止值";
CM_ SG_ 2417290822 S2P_Lmt12_Over_Icharge1_06 "电池簇充电电流一级报警值";
CM_ SG_ 2417290822 S2P_Lmt12_Over_Icharge2_06 "电池簇充电电流二级报警值";
CM_ SG_ 2417290822 S2P_Lmt12_Over_Icharge3_06 "电池簇充电电流三级报警值";
CM_ SG_ 2417290822 S2P_Lmt12_Over_Icharge4_06 "电池簇充电电流截止值";
CM_ SG_ 2417290823 S2P_Lmt12_Over_Icharge1_07 "电池簇充电电流一级报警值";
CM_ SG_ 2417290823 S2P_Lmt12_Over_Icharge2_07 "电池簇充电电流二级报警值";
CM_ SG_ 2417290823 S2P_Lmt12_Over_Icharge3_07 "电池簇充电电流三级报警值";
CM_ SG_ 2417290823 S2P_Lmt12_Over_Icharge4_07 "电池簇充电电流截止值";
CM_ SG_ 2417290824 S2P_Lmt12_Over_Icharge1_08 "电池簇充电电流一级报警值";
CM_ SG_ 2417290824 S2P_Lmt12_Over_Icharge2_08 "电池簇充电电流二级报警值";
CM_ SG_ 2417290824 S2P_Lmt12_Over_Icharge3_08 "电池簇充电电流三级报警值";
CM_ SG_ 2417290824 S2P_Lmt12_Over_Icharge4_08 "电池簇充电电流截止值";
CM_ SG_ 2417290825 S2P_Lmt12_Over_Icharge1_09 "电池簇充电电流一级报警值";
CM_ SG_ 2417290825 S2P_Lmt12_Over_Icharge2_09 "电池簇充电电流二级报警值";
CM_ SG_ 2417290825 S2P_Lmt12_Over_Icharge3_09 "电池簇充电电流三级报警值";
CM_ SG_ 2417290825 S2P_Lmt12_Over_Icharge4_09 "电池簇充电电流截止值";
CM_ SG_ 2417290826 S2P_Lmt12_Over_Icharge1_10 "电池簇充电电流一级报警值";
CM_ SG_ 2417290826 S2P_Lmt12_Over_Icharge2_10 "电池簇充电电流二级报警值";
CM_ SG_ 2417290826 S2P_Lmt12_Over_Icharge3_10 "电池簇充电电流三级报警值";
CM_ SG_ 2417290826 S2P_Lmt12_Over_Icharge4_10 "电池簇充电电流截止值";
CM_ SG_ 2417290827 S2P_Lmt12_Over_Icharge1_11 "电池簇充电电流一级报警值";
CM_ SG_ 2417290827 S2P_Lmt12_Over_Icharge2_11 "电池簇充电电流二级报警值";
CM_ SG_ 2417290827 S2P_Lmt12_Over_Icharge3_11 "电池簇充电电流三级报警值";
CM_ SG_ 2417290827 S2P_Lmt12_Over_Icharge4_11 "电池簇充电电流截止值";
CM_ SG_ 2417290828 S2P_Lmt12_Over_Icharge1_12 "电池簇充电电流一级报警值";
CM_ SG_ 2417290828 S2P_Lmt12_Over_Icharge2_12 "电池簇充电电流二级报警值";
CM_ SG_ 2417290828 S2P_Lmt12_Over_Icharge3_12 "电池簇充电电流三级报警值";
CM_ SG_ 2417290828 S2P_Lmt12_Over_Icharge4_12 "电池簇充电电流截止值";
CM_ SG_ 2417290829 S2P_Lmt12_Over_Icharge1_13 "电池簇充电电流一级报警值";
CM_ SG_ 2417290829 S2P_Lmt12_Over_Icharge2_13 "电池簇充电电流二级报警值";
CM_ SG_ 2417290829 S2P_Lmt12_Over_Icharge3_13 "电池簇充电电流三级报警值";
CM_ SG_ 2417290829 S2P_Lmt12_Over_Icharge4_13 "电池簇充电电流截止值";
CM_ SG_ 2417290830 S2P_Lmt12_Over_Icharge1_14 "电池簇充电电流一级报警值";
CM_ SG_ 2417290830 S2P_Lmt12_Over_Icharge2_14 "电池簇充电电流二级报警值";
CM_ SG_ 2417290830 S2P_Lmt12_Over_Icharge3_14 "电池簇充电电流三级报警值";
CM_ SG_ 2417290830 S2P_Lmt12_Over_Icharge4_14 "电池簇充电电流截止值";
CM_ SG_ 2417290831 S2P_Lmt12_Over_Icharge1_15 "电池簇充电电流一级报警值";
CM_ SG_ 2417290831 S2P_Lmt12_Over_Icharge2_15 "电池簇充电电流二级报警值";
CM_ SG_ 2417290831 S2P_Lmt12_Over_Icharge3_15 "电池簇充电电流三级报警值";
CM_ SG_ 2417290831 S2P_Lmt12_Over_Icharge4_15 "电池簇充电电流截止值";
CM_ SG_ 2417290832 S2P_Lmt12_Over_Icharge1_16 "电池簇充电电流一级报警值";
CM_ SG_ 2417290832 S2P_Lmt12_Over_Icharge2_16 "电池簇充电电流二级报警值";
CM_ SG_ 2417290832 S2P_Lmt12_Over_Icharge3_16 "电池簇充电电流三级报警值";
CM_ SG_ 2417290832 S2P_Lmt12_Over_Icharge4_16 "电池簇充电电流截止值";
CM_ SG_ 2417290833 S2P_Lmt12_Over_Icharge1_17 "电池簇充电电流一级报警值";
CM_ SG_ 2417290833 S2P_Lmt12_Over_Icharge2_17 "电池簇充电电流二级报警值";
CM_ SG_ 2417290833 S2P_Lmt12_Over_Icharge3_17 "电池簇充电电流三级报警值";
CM_ SG_ 2417290833 S2P_Lmt12_Over_Icharge4_17 "电池簇充电电流截止值";
CM_ SG_ 2417290834 S2P_Lmt12_Over_Icharge1_18 "电池簇充电电流一级报警值";
CM_ SG_ 2417290834 S2P_Lmt12_Over_Icharge2_18 "电池簇充电电流二级报警值";
CM_ SG_ 2417290834 S2P_Lmt12_Over_Icharge3_18 "电池簇充电电流三级报警值";
CM_ SG_ 2417290834 S2P_Lmt12_Over_Icharge4_18 "电池簇充电电流截止值";
CM_ SG_ 2417290835 S2P_Lmt12_Over_Icharge1_19 "电池簇充电电流一级报警值";
CM_ SG_ 2417290835 S2P_Lmt12_Over_Icharge2_19 "电池簇充电电流二级报警值";
CM_ SG_ 2417290835 S2P_Lmt12_Over_Icharge3_19 "电池簇充电电流三级报警值";
CM_ SG_ 2417290835 S2P_Lmt12_Over_Icharge4_19 "电池簇充电电流截止值";
CM_ SG_ 2417290836 S2P_Lmt12_Over_Icharge1_20 "电池簇充电电流一级报警值";
CM_ SG_ 2417290836 S2P_Lmt12_Over_Icharge2_20 "电池簇充电电流二级报警值";
CM_ SG_ 2417290836 S2P_Lmt12_Over_Icharge3_20 "电池簇充电电流三级报警值";
CM_ SG_ 2417290836 S2P_Lmt12_Over_Icharge4_20 "电池簇充电电流截止值";
CM_ SG_ 2417290837 S2P_Lmt12_Over_Icharge1_21 "电池簇充电电流一级报警值";
CM_ SG_ 2417290837 S2P_Lmt12_Over_Icharge2_21 "电池簇充电电流二级报警值";
CM_ SG_ 2417290837 S2P_Lmt12_Over_Icharge3_21 "电池簇充电电流三级报警值";
CM_ SG_ 2417290837 S2P_Lmt12_Over_Icharge4_21 "电池簇充电电流截止值";
CM_ SG_ 2417290838 S2P_Lmt12_Over_Icharge1_22 "电池簇充电电流一级报警值";
CM_ SG_ 2417290838 S2P_Lmt12_Over_Icharge2_22 "电池簇充电电流二级报警值";
CM_ SG_ 2417290838 S2P_Lmt12_Over_Icharge3_22 "电池簇充电电流三级报警值";
CM_ SG_ 2417290838 S2P_Lmt12_Over_Icharge4_22 "电池簇充电电流截止值";
CM_ SG_ 2417290839 S2P_Lmt12_Over_Icharge1_23 "电池簇充电电流一级报警值";
CM_ SG_ 2417290839 S2P_Lmt12_Over_Icharge2_23 "电池簇充电电流二级报警值";
CM_ SG_ 2417290839 S2P_Lmt12_Over_Icharge3_23 "电池簇充电电流三级报警值";
CM_ SG_ 2417290839 S2P_Lmt12_Over_Icharge4_23 "电池簇充电电流截止值";
CM_ SG_ 2417290840 S2P_Lmt12_Over_Icharge1_24 "电池簇充电电流一级报警值";
CM_ SG_ 2417290840 S2P_Lmt12_Over_Icharge2_24 "电池簇充电电流二级报警值";
CM_ SG_ 2417290840 S2P_Lmt12_Over_Icharge3_24 "电池簇充电电流三级报警值";
CM_ SG_ 2417290840 S2P_Lmt12_Over_Icharge4_24 "电池簇充电电流截止值";
CM_ SG_ 2417290841 S2P_Lmt12_Over_Icharge1_25 "电池簇充电电流一级报警值";
CM_ SG_ 2417290841 S2P_Lmt12_Over_Icharge2_25 "电池簇充电电流二级报警值";
CM_ SG_ 2417290841 S2P_Lmt12_Over_Icharge3_25 "电池簇充电电流三级报警值";
CM_ SG_ 2417290841 S2P_Lmt12_Over_Icharge4_25 "电池簇充电电流截止值";
CM_ SG_ 2417290842 S2P_Lmt12_Over_Icharge1_26 "电池簇充电电流一级报警值";
CM_ SG_ 2417290842 S2P_Lmt12_Over_Icharge2_26 "电池簇充电电流二级报警值";
CM_ SG_ 2417290842 S2P_Lmt12_Over_Icharge3_26 "电池簇充电电流三级报警值";
CM_ SG_ 2417290842 S2P_Lmt12_Over_Icharge4_26 "电池簇充电电流截止值";
CM_ SG_ 2417290843 S2P_Lmt12_Over_Icharge1_27 "电池簇充电电流一级报警值";
CM_ SG_ 2417290843 S2P_Lmt12_Over_Icharge2_27 "电池簇充电电流二级报警值";
CM_ SG_ 2417290843 S2P_Lmt12_Over_Icharge3_27 "电池簇充电电流三级报警值";
CM_ SG_ 2417290843 S2P_Lmt12_Over_Icharge4_27 "电池簇充电电流截止值";
CM_ SG_ 2417290844 S2P_Lmt12_Over_Icharge1_28 "电池簇充电电流一级报警值";
CM_ SG_ 2417290844 S2P_Lmt12_Over_Icharge2_28 "电池簇充电电流二级报警值";
CM_ SG_ 2417290844 S2P_Lmt12_Over_Icharge3_28 "电池簇充电电流三级报警值";
CM_ SG_ 2417290844 S2P_Lmt12_Over_Icharge4_28 "电池簇充电电流截止值";
CM_ SG_ 2417290845 S2P_Lmt12_Over_Icharge1_29 "电池簇充电电流一级报警值";
CM_ SG_ 2417290845 S2P_Lmt12_Over_Icharge2_29 "电池簇充电电流二级报警值";
CM_ SG_ 2417290845 S2P_Lmt12_Over_Icharge3_29 "电池簇充电电流三级报警值";
CM_ SG_ 2417290845 S2P_Lmt12_Over_Icharge4_29 "电池簇充电电流截止值";
CM_ SG_ 2417290846 S2P_Lmt12_Over_Icharge1_30 "电池簇充电电流一级报警值";
CM_ SG_ 2417290846 S2P_Lmt12_Over_Icharge2_30 "电池簇充电电流二级报警值";
CM_ SG_ 2417290846 S2P_Lmt12_Over_Icharge3_30 "电池簇充电电流三级报警值";
CM_ SG_ 2417290846 S2P_Lmt12_Over_Icharge4_30 "电池簇充电电流截止值";
CM_ SG_ 2417290847 S2P_Lmt12_Over_Icharge1_31 "电池簇充电电流一级报警值";
CM_ SG_ 2417290847 S2P_Lmt12_Over_Icharge2_31 "电池簇充电电流二级报警值";
CM_ SG_ 2417290847 S2P_Lmt12_Over_Icharge3_31 "电池簇充电电流三级报警值";
CM_ SG_ 2417290847 S2P_Lmt12_Over_Icharge4_31 "电池簇充电电流截止值";
CM_ SG_ 2417290848 S2P_Lmt12_Over_Icharge1_32 "电池簇充电电流一级报警值";
CM_ SG_ 2417290848 S2P_Lmt12_Over_Icharge2_32 "电池簇充电电流二级报警值";
CM_ SG_ 2417290848 S2P_Lmt12_Over_Icharge3_32 "电池簇充电电流三级报警值";
CM_ SG_ 2417290848 S2P_Lmt12_Over_Icharge4_32 "电池簇充电电流截止值";
CM_ SG_ 2417290849 S2P_Lmt12_Over_Icharge1_33 "电池簇充电电流一级报警值";
CM_ SG_ 2417290849 S2P_Lmt12_Over_Icharge2_33 "电池簇充电电流二级报警值";
CM_ SG_ 2417290849 S2P_Lmt12_Over_Icharge3_33 "电池簇充电电流三级报警值";
CM_ SG_ 2417290849 S2P_Lmt12_Over_Icharge4_33 "电池簇充电电流截止值";
CM_ SG_ 2417290850 S2P_Lmt12_Over_Icharge1_34 "电池簇充电电流一级报警值";
CM_ SG_ 2417290850 S2P_Lmt12_Over_Icharge2_34 "电池簇充电电流二级报警值";
CM_ SG_ 2417290850 S2P_Lmt12_Over_Icharge3_34 "电池簇充电电流三级报警值";
CM_ SG_ 2417290850 S2P_Lmt12_Over_Icharge4_34 "电池簇充电电流截止值";
CM_ SG_ 2417290851 S2P_Lmt12_Over_Icharge1_35 "电池簇充电电流一级报警值";
CM_ SG_ 2417290851 S2P_Lmt12_Over_Icharge2_35 "电池簇充电电流二级报警值";
CM_ SG_ 2417290851 S2P_Lmt12_Over_Icharge3_35 "电池簇充电电流三级报警值";
CM_ SG_ 2417290851 S2P_Lmt12_Over_Icharge4_35 "电池簇充电电流截止值";
CM_ SG_ 2417290852 S2P_Lmt12_Over_Icharge1_36 "电池簇充电电流一级报警值";
CM_ SG_ 2417290852 S2P_Lmt12_Over_Icharge2_36 "电池簇充电电流二级报警值";
CM_ SG_ 2417290852 S2P_Lmt12_Over_Icharge3_36 "电池簇充电电流三级报警值";
CM_ SG_ 2417290852 S2P_Lmt12_Over_Icharge4_36 "电池簇充电电流截止值";
CM_ SG_ 2417290853 S2P_Lmt12_Over_Icharge1_37 "电池簇充电电流一级报警值";
CM_ SG_ 2417290853 S2P_Lmt12_Over_Icharge2_37 "电池簇充电电流二级报警值";
CM_ SG_ 2417290853 S2P_Lmt12_Over_Icharge3_37 "电池簇充电电流三级报警值";
CM_ SG_ 2417290853 S2P_Lmt12_Over_Icharge4_37 "电池簇充电电流截止值";
CM_ SG_ 2417290854 S2P_Lmt12_Over_Icharge1_38 "电池簇充电电流一级报警值";
CM_ SG_ 2417290854 S2P_Lmt12_Over_Icharge2_38 "电池簇充电电流二级报警值";
CM_ SG_ 2417290854 S2P_Lmt12_Over_Icharge3_38 "电池簇充电电流三级报警值";
CM_ SG_ 2417290854 S2P_Lmt12_Over_Icharge4_38 "电池簇充电电流截止值";
CM_ SG_ 2417290855 S2P_Lmt12_Over_Icharge1_39 "电池簇充电电流一级报警值";
CM_ SG_ 2417290855 S2P_Lmt12_Over_Icharge2_39 "电池簇充电电流二级报警值";
CM_ SG_ 2417290855 S2P_Lmt12_Over_Icharge3_39 "电池簇充电电流三级报警值";
CM_ SG_ 2417290855 S2P_Lmt12_Over_Icharge4_39 "电池簇充电电流截止值";
CM_ SG_ 2417290856 S2P_Lmt12_Over_Icharge1_40 "电池簇充电电流一级报警值";
CM_ SG_ 2417290856 S2P_Lmt12_Over_Icharge2_40 "电池簇充电电流二级报警值";
CM_ SG_ 2417290856 S2P_Lmt12_Over_Icharge3_40 "电池簇充电电流三级报警值";
CM_ SG_ 2417290856 S2P_Lmt12_Over_Icharge4_40 "电池簇充电电流截止值";
CM_ SG_ 2417290857 S2P_Lmt12_Over_Icharge1_41 "电池簇充电电流一级报警值";
CM_ SG_ 2417290857 S2P_Lmt12_Over_Icharge2_41 "电池簇充电电流二级报警值";
CM_ SG_ 2417290857 S2P_Lmt12_Over_Icharge3_41 "电池簇充电电流三级报警值";
CM_ SG_ 2417290857 S2P_Lmt12_Over_Icharge4_41 "电池簇充电电流截止值";
CM_ SG_ 2417290858 S2P_Lmt12_Over_Icharge1_42 "电池簇充电电流一级报警值";
CM_ SG_ 2417290858 S2P_Lmt12_Over_Icharge2_42 "电池簇充电电流二级报警值";
CM_ SG_ 2417290858 S2P_Lmt12_Over_Icharge3_42 "电池簇充电电流三级报警值";
CM_ SG_ 2417290858 S2P_Lmt12_Over_Icharge4_42 "电池簇充电电流截止值";
CM_ SG_ 2417290859 S2P_Lmt12_Over_Icharge1_43 "电池簇充电电流一级报警值";
CM_ SG_ 2417290859 S2P_Lmt12_Over_Icharge2_43 "电池簇充电电流二级报警值";
CM_ SG_ 2417290859 S2P_Lmt12_Over_Icharge3_43 "电池簇充电电流三级报警值";
CM_ SG_ 2417290859 S2P_Lmt12_Over_Icharge4_43 "电池簇充电电流截止值";
CM_ SG_ 2417290860 S2P_Lmt12_Over_Icharge1_44 "电池簇充电电流一级报警值";
CM_ SG_ 2417290860 S2P_Lmt12_Over_Icharge2_44 "电池簇充电电流二级报警值";
CM_ SG_ 2417290860 S2P_Lmt12_Over_Icharge3_44 "电池簇充电电流三级报警值";
CM_ SG_ 2417290860 S2P_Lmt12_Over_Icharge4_44 "电池簇充电电流截止值";
CM_ SG_ 2417290861 S2P_Lmt12_Over_Icharge1_45 "电池簇充电电流一级报警值";
CM_ SG_ 2417290861 S2P_Lmt12_Over_Icharge2_45 "电池簇充电电流二级报警值";
CM_ SG_ 2417290861 S2P_Lmt12_Over_Icharge3_45 "电池簇充电电流三级报警值";
CM_ SG_ 2417290861 S2P_Lmt12_Over_Icharge4_45 "电池簇充电电流截止值";
CM_ SG_ 2417290862 S2P_Lmt12_Over_Icharge1_46 "电池簇充电电流一级报警值";
CM_ SG_ 2417290862 S2P_Lmt12_Over_Icharge2_46 "电池簇充电电流二级报警值";
CM_ SG_ 2417290862 S2P_Lmt12_Over_Icharge3_46 "电池簇充电电流三级报警值";
CM_ SG_ 2417290862 S2P_Lmt12_Over_Icharge4_46 "电池簇充电电流截止值";
CM_ SG_ 2417290863 S2P_Lmt12_Over_Icharge1_47 "电池簇充电电流一级报警值";
CM_ SG_ 2417290863 S2P_Lmt12_Over_Icharge2_47 "电池簇充电电流二级报警值";
CM_ SG_ 2417290863 S2P_Lmt12_Over_Icharge3_47 "电池簇充电电流三级报警值";
CM_ SG_ 2417290863 S2P_Lmt12_Over_Icharge4_47 "电池簇充电电流截止值";
CM_ SG_ 2417290864 S2P_Lmt12_Over_Icharge1_48 "电池簇充电电流一级报警值";
CM_ SG_ 2417290864 S2P_Lmt12_Over_Icharge2_48 "电池簇充电电流二级报警值";
CM_ SG_ 2417290864 S2P_Lmt12_Over_Icharge3_48 "电池簇充电电流三级报警值";
CM_ SG_ 2417290864 S2P_Lmt12_Over_Icharge4_48 "电池簇充电电流截止值";
CM_ SG_ 2417290865 S2P_Lmt12_Over_Icharge1_49 "电池簇充电电流一级报警值";
CM_ SG_ 2417290865 S2P_Lmt12_Over_Icharge2_49 "电池簇充电电流二级报警值";
CM_ SG_ 2417290865 S2P_Lmt12_Over_Icharge3_49 "电池簇充电电流三级报警值";
CM_ SG_ 2417290865 S2P_Lmt12_Over_Icharge4_49 "电池簇充电电流截止值";
CM_ SG_ 2417290866 S2P_Lmt12_Over_Icharge1_50 "电池簇充电电流一级报警值";
CM_ SG_ 2417290866 S2P_Lmt12_Over_Icharge2_50 "电池簇充电电流二级报警值";
CM_ SG_ 2417290866 S2P_Lmt12_Over_Icharge3_50 "电池簇充电电流三级报警值";
CM_ SG_ 2417290866 S2P_Lmt12_Over_Icharge4_50 "电池簇充电电流截止值";
CM_ SG_ 2417290867 S2P_Lmt12_Over_Icharge1_51 "电池簇充电电流一级报警值";
CM_ SG_ 2417290867 S2P_Lmt12_Over_Icharge2_51 "电池簇充电电流二级报警值";
CM_ SG_ 2417290867 S2P_Lmt12_Over_Icharge3_51 "电池簇充电电流三级报警值";
CM_ SG_ 2417290867 S2P_Lmt12_Over_Icharge4_51 "电池簇充电电流截止值";
CM_ SG_ 2417290868 S2P_Lmt12_Over_Icharge1_52 "电池簇充电电流一级报警值";
CM_ SG_ 2417290868 S2P_Lmt12_Over_Icharge2_52 "电池簇充电电流二级报警值";
CM_ SG_ 2417290868 S2P_Lmt12_Over_Icharge3_52 "电池簇充电电流三级报警值";
CM_ SG_ 2417290868 S2P_Lmt12_Over_Icharge4_52 "电池簇充电电流截止值";
CM_ SG_ 2417290869 S2P_Lmt12_Over_Icharge1_53 "电池簇充电电流一级报警值";
CM_ SG_ 2417290869 S2P_Lmt12_Over_Icharge2_53 "电池簇充电电流二级报警值";
CM_ SG_ 2417290869 S2P_Lmt12_Over_Icharge3_53 "电池簇充电电流三级报警值";
CM_ SG_ 2417290869 S2P_Lmt12_Over_Icharge4_53 "电池簇充电电流截止值";
CM_ SG_ 2417290870 S2P_Lmt12_Over_Icharge1_54 "电池簇充电电流一级报警值";
CM_ SG_ 2417290870 S2P_Lmt12_Over_Icharge2_54 "电池簇充电电流二级报警值";
CM_ SG_ 2417290870 S2P_Lmt12_Over_Icharge3_54 "电池簇充电电流三级报警值";
CM_ SG_ 2417290870 S2P_Lmt12_Over_Icharge4_54 "电池簇充电电流截止值";
CM_ SG_ 2417290871 S2P_Lmt12_Over_Icharge1_55 "电池簇充电电流一级报警值";
CM_ SG_ 2417290871 S2P_Lmt12_Over_Icharge2_55 "电池簇充电电流二级报警值";
CM_ SG_ 2417290871 S2P_Lmt12_Over_Icharge3_55 "电池簇充电电流三级报警值";
CM_ SG_ 2417290871 S2P_Lmt12_Over_Icharge4_55 "电池簇充电电流截止值";
CM_ SG_ 2417290872 S2P_Lmt12_Over_Icharge1_56 "电池簇充电电流一级报警值";
CM_ SG_ 2417290872 S2P_Lmt12_Over_Icharge2_56 "电池簇充电电流二级报警值";
CM_ SG_ 2417290872 S2P_Lmt12_Over_Icharge3_56 "电池簇充电电流三级报警值";
CM_ SG_ 2417290872 S2P_Lmt12_Over_Icharge4_56 "电池簇充电电流截止值";
CM_ SG_ 2417290873 S2P_Lmt12_Over_Icharge1_57 "电池簇充电电流一级报警值";
CM_ SG_ 2417290873 S2P_Lmt12_Over_Icharge2_57 "电池簇充电电流二级报警值";
CM_ SG_ 2417290873 S2P_Lmt12_Over_Icharge3_57 "电池簇充电电流三级报警值";
CM_ SG_ 2417290873 S2P_Lmt12_Over_Icharge4_57 "电池簇充电电流截止值";
CM_ SG_ 2417290874 S2P_Lmt12_Over_Icharge1_58 "电池簇充电电流一级报警值";
CM_ SG_ 2417290874 S2P_Lmt12_Over_Icharge2_58 "电池簇充电电流二级报警值";
CM_ SG_ 2417290874 S2P_Lmt12_Over_Icharge3_58 "电池簇充电电流三级报警值";
CM_ SG_ 2417290874 S2P_Lmt12_Over_Icharge4_58 "电池簇充电电流截止值";
CM_ SG_ 2417290875 S2P_Lmt12_Over_Icharge1_59 "电池簇充电电流一级报警值";
CM_ SG_ 2417290875 S2P_Lmt12_Over_Icharge2_59 "电池簇充电电流二级报警值";
CM_ SG_ 2417290875 S2P_Lmt12_Over_Icharge3_59 "电池簇充电电流三级报警值";
CM_ SG_ 2417290875 S2P_Lmt12_Over_Icharge4_59 "电池簇充电电流截止值";
CM_ SG_ 2417290876 S2P_Lmt12_Over_Icharge1_60 "电池簇充电电流一级报警值";
CM_ SG_ 2417290876 S2P_Lmt12_Over_Icharge2_60 "电池簇充电电流二级报警值";
CM_ SG_ 2417290876 S2P_Lmt12_Over_Icharge3_60 "电池簇充电电流三级报警值";
CM_ SG_ 2417290876 S2P_Lmt12_Over_Icharge4_60 "电池簇充电电流截止值";
CM_ SG_ 2417290877 S2P_Lmt12_Over_Icharge1_61 "电池簇充电电流一级报警值";
CM_ SG_ 2417290877 S2P_Lmt12_Over_Icharge2_61 "电池簇充电电流二级报警值";
CM_ SG_ 2417290877 S2P_Lmt12_Over_Icharge3_61 "电池簇充电电流三级报警值";
CM_ SG_ 2417290877 S2P_Lmt12_Over_Icharge4_61 "电池簇充电电流截止值";
CM_ SG_ 2417290878 S2P_Lmt12_Over_Icharge1_62 "电池簇充电电流一级报警值";
CM_ SG_ 2417290878 S2P_Lmt12_Over_Icharge2_62 "电池簇充电电流二级报警值";
CM_ SG_ 2417290878 S2P_Lmt12_Over_Icharge3_62 "电池簇充电电流三级报警值";
CM_ SG_ 2417290878 S2P_Lmt12_Over_Icharge4_62 "电池簇充电电流截止值";
CM_ SG_ 2417290879 S2P_Lmt12_Over_Icharge1_63 "电池簇充电电流一级报警值";
CM_ SG_ 2417290879 S2P_Lmt12_Over_Icharge2_63 "电池簇充电电流二级报警值";
CM_ SG_ 2417290879 S2P_Lmt12_Over_Icharge3_63 "电池簇充电电流三级报警值";
CM_ SG_ 2417290879 S2P_Lmt12_Over_Icharge4_63 "电池簇充电电流截止值";
CM_ SG_ 2417356353 S2P_Lmt13_Over_SOC1_01 "SOC过高1级告警阈值";
CM_ SG_ 2417356353 S2P_Lmt13_Over_SOC2_01 "SOC过高2级告警阈值";
CM_ SG_ 2417356353 S2P_Lmt13_Over_SOC3_01 "SOC过高3级告警阈值";
CM_ SG_ 2417356353 S2P_Lmt13_Over_DSOC_01 "SOC过高告警消除回差阈值";
CM_ SG_ 2417356354 S2P_Lmt13_Over_SOC1_02 "SOC过高1级告警阈值";
CM_ SG_ 2417356354 S2P_Lmt13_Over_SOC2_02 "SOC过高2级告警阈值";
CM_ SG_ 2417356354 S2P_Lmt13_Over_SOC3_02 "SOC过高3级告警阈值";
CM_ SG_ 2417356354 S2P_Lmt13_Over_DSOC_02 "SOC过高告警消除回差阈值";
CM_ SG_ 2417356355 S2P_Lmt13_Over_SOC1_03 "SOC过高1级告警阈值";
CM_ SG_ 2417356355 S2P_Lmt13_Over_SOC2_03 "SOC过高2级告警阈值";
CM_ SG_ 2417356355 S2P_Lmt13_Over_SOC3_03 "SOC过高3级告警阈值";
CM_ SG_ 2417356355 S2P_Lmt13_Over_DSOC_03 "SOC过高告警消除回差阈值";
CM_ SG_ 2417356356 S2P_Lmt13_Over_SOC1_04 "SOC过高1级告警阈值";
CM_ SG_ 2417356356 S2P_Lmt13_Over_SOC2_04 "SOC过高2级告警阈值";
CM_ SG_ 2417356356 S2P_Lmt13_Over_SOC3_04 "SOC过高3级告警阈值";
CM_ SG_ 2417356356 S2P_Lmt13_Over_DSOC_04 "SOC过高告警消除回差阈值";
CM_ SG_ 2417356357 S2P_Lmt13_Over_SOC1_05 "SOC过高1级告警阈值";
CM_ SG_ 2417356357 S2P_Lmt13_Over_SOC2_05 "SOC过高2级告警阈值";
CM_ SG_ 2417356357 S2P_Lmt13_Over_SOC3_05 "SOC过高3级告警阈值";
CM_ SG_ 2417356357 S2P_Lmt13_Over_DSOC_05 "SOC过高告警消除回差阈值";
CM_ SG_ 2417356358 S2P_Lmt13_Over_SOC1_06 "SOC过高1级告警阈值";
CM_ SG_ 2417356358 S2P_Lmt13_Over_SOC2_06 "SOC过高2级告警阈值";
CM_ SG_ 2417356358 S2P_Lmt13_Over_SOC3_06 "SOC过高3级告警阈值";
CM_ SG_ 2417356358 S2P_Lmt13_Over_DSOC_06 "SOC过高告警消除回差阈值";
CM_ SG_ 2417356359 S2P_Lmt13_Over_SOC1_07 "SOC过高1级告警阈值";
CM_ SG_ 2417356359 S2P_Lmt13_Over_SOC2_07 "SOC过高2级告警阈值";
CM_ SG_ 2417356359 S2P_Lmt13_Over_SOC3_07 "SOC过高3级告警阈值";
CM_ SG_ 2417356359 S2P_Lmt13_Over_DSOC_07 "SOC过高告警消除回差阈值";
CM_ SG_ 2417356360 S2P_Lmt13_Over_SOC1_08 "SOC过高1级告警阈值";
CM_ SG_ 2417356360 S2P_Lmt13_Over_SOC2_08 "SOC过高2级告警阈值";
CM_ SG_ 2417356360 S2P_Lmt13_Over_SOC3_08 "SOC过高3级告警阈值";
CM_ SG_ 2417356360 S2P_Lmt13_Over_DSOC_08 "SOC过高告警消除回差阈值";
CM_ SG_ 2417356361 S2P_Lmt13_Over_SOC1_09 "SOC过高1级告警阈值";
CM_ SG_ 2417356361 S2P_Lmt13_Over_SOC2_09 "SOC过高2级告警阈值";
CM_ SG_ 2417356361 S2P_Lmt13_Over_SOC3_09 "SOC过高3级告警阈值";
CM_ SG_ 2417356361 S2P_Lmt13_Over_DSOC_09 "SOC过高告警消除回差阈值";
CM_ SG_ 2417356362 S2P_Lmt13_Over_SOC1_10 "SOC过高1级告警阈值";
CM_ SG_ 2417356362 S2P_Lmt13_Over_SOC2_10 "SOC过高2级告警阈值";
CM_ SG_ 2417356362 S2P_Lmt13_Over_SOC3_10 "SOC过高3级告警阈值";
CM_ SG_ 2417356362 S2P_Lmt13_Over_DSOC_10 "SOC过高告警消除回差阈值";
CM_ SG_ 2417356363 S2P_Lmt13_Over_SOC1_11 "SOC过高1级告警阈值";
CM_ SG_ 2417356363 S2P_Lmt13_Over_SOC2_11 "SOC过高2级告警阈值";
CM_ SG_ 2417356363 S2P_Lmt13_Over_SOC3_11 "SOC过高3级告警阈值";
CM_ SG_ 2417356363 S2P_Lmt13_Over_DSOC_11 "SOC过高告警消除回差阈值";
CM_ SG_ 2417356364 S2P_Lmt13_Over_SOC1_12 "SOC过高1级告警阈值";
CM_ SG_ 2417356364 S2P_Lmt13_Over_SOC2_12 "SOC过高2级告警阈值";
CM_ SG_ 2417356364 S2P_Lmt13_Over_SOC3_12 "SOC过高3级告警阈值";
CM_ SG_ 2417356364 S2P_Lmt13_Over_DSOC_12 "SOC过高告警消除回差阈值";
CM_ SG_ 2417356365 S2P_Lmt13_Over_SOC1_13 "SOC过高1级告警阈值";
CM_ SG_ 2417356365 S2P_Lmt13_Over_SOC2_13 "SOC过高2级告警阈值";
CM_ SG_ 2417356365 S2P_Lmt13_Over_SOC3_13 "SOC过高3级告警阈值";
CM_ SG_ 2417356365 S2P_Lmt13_Over_DSOC_13 "SOC过高告警消除回差阈值";
CM_ SG_ 2417356366 S2P_Lmt13_Over_SOC1_14 "SOC过高1级告警阈值";
CM_ SG_ 2417356366 S2P_Lmt13_Over_SOC2_14 "SOC过高2级告警阈值";
CM_ SG_ 2417356366 S2P_Lmt13_Over_SOC3_14 "SOC过高3级告警阈值";
CM_ SG_ 2417356366 S2P_Lmt13_Over_DSOC_14 "SOC过高告警消除回差阈值";
CM_ SG_ 2417356367 S2P_Lmt13_Over_SOC1_15 "SOC过高1级告警阈值";
CM_ SG_ 2417356367 S2P_Lmt13_Over_SOC2_15 "SOC过高2级告警阈值";
CM_ SG_ 2417356367 S2P_Lmt13_Over_SOC3_15 "SOC过高3级告警阈值";
CM_ SG_ 2417356367 S2P_Lmt13_Over_DSOC_15 "SOC过高告警消除回差阈值";
CM_ SG_ 2417356368 S2P_Lmt13_Over_SOC1_16 "SOC过高1级告警阈值";
CM_ SG_ 2417356368 S2P_Lmt13_Over_SOC2_16 "SOC过高2级告警阈值";
CM_ SG_ 2417356368 S2P_Lmt13_Over_SOC3_16 "SOC过高3级告警阈值";
CM_ SG_ 2417356368 S2P_Lmt13_Over_DSOC_16 "SOC过高告警消除回差阈值";
CM_ SG_ 2417356369 S2P_Lmt13_Over_SOC1_17 "SOC过高1级告警阈值";
CM_ SG_ 2417356369 S2P_Lmt13_Over_SOC2_17 "SOC过高2级告警阈值";
CM_ SG_ 2417356369 S2P_Lmt13_Over_SOC3_17 "SOC过高3级告警阈值";
CM_ SG_ 2417356369 S2P_Lmt13_Over_DSOC_17 "SOC过高告警消除回差阈值";
CM_ SG_ 2417356370 S2P_Lmt13_Over_SOC1_18 "SOC过高1级告警阈值";
CM_ SG_ 2417356370 S2P_Lmt13_Over_SOC2_18 "SOC过高2级告警阈值";
CM_ SG_ 2417356370 S2P_Lmt13_Over_SOC3_18 "SOC过高3级告警阈值";
CM_ SG_ 2417356370 S2P_Lmt13_Over_DSOC_18 "SOC过高告警消除回差阈值";
CM_ SG_ 2417356371 S2P_Lmt13_Over_SOC1_19 "SOC过高1级告警阈值";
CM_ SG_ 2417356371 S2P_Lmt13_Over_SOC2_19 "SOC过高2级告警阈值";
CM_ SG_ 2417356371 S2P_Lmt13_Over_SOC3_19 "SOC过高3级告警阈值";
CM_ SG_ 2417356371 S2P_Lmt13_Over_DSOC_19 "SOC过高告警消除回差阈值";
CM_ SG_ 2417356372 S2P_Lmt13_Over_SOC1_20 "SOC过高1级告警阈值";
CM_ SG_ 2417356372 S2P_Lmt13_Over_SOC2_20 "SOC过高2级告警阈值";
CM_ SG_ 2417356372 S2P_Lmt13_Over_SOC3_20 "SOC过高3级告警阈值";
CM_ SG_ 2417356372 S2P_Lmt13_Over_DSOC_20 "SOC过高告警消除回差阈值";
CM_ SG_ 2417356373 S2P_Lmt13_Over_SOC1_21 "SOC过高1级告警阈值";
CM_ SG_ 2417356373 S2P_Lmt13_Over_SOC2_21 "SOC过高2级告警阈值";
CM_ SG_ 2417356373 S2P_Lmt13_Over_SOC3_21 "SOC过高3级告警阈值";
CM_ SG_ 2417356373 S2P_Lmt13_Over_DSOC_21 "SOC过高告警消除回差阈值";
CM_ SG_ 2417356374 S2P_Lmt13_Over_SOC1_22 "SOC过高1级告警阈值";
CM_ SG_ 2417356374 S2P_Lmt13_Over_SOC2_22 "SOC过高2级告警阈值";
CM_ SG_ 2417356374 S2P_Lmt13_Over_SOC3_22 "SOC过高3级告警阈值";
CM_ SG_ 2417356374 S2P_Lmt13_Over_DSOC_22 "SOC过高告警消除回差阈值";
CM_ SG_ 2417356375 S2P_Lmt13_Over_SOC1_23 "SOC过高1级告警阈值";
CM_ SG_ 2417356375 S2P_Lmt13_Over_SOC2_23 "SOC过高2级告警阈值";
CM_ SG_ 2417356375 S2P_Lmt13_Over_SOC3_23 "SOC过高3级告警阈值";
CM_ SG_ 2417356375 S2P_Lmt13_Over_DSOC_23 "SOC过高告警消除回差阈值";
CM_ SG_ 2417356376 S2P_Lmt13_Over_SOC1_24 "SOC过高1级告警阈值";
CM_ SG_ 2417356376 S2P_Lmt13_Over_SOC2_24 "SOC过高2级告警阈值";
CM_ SG_ 2417356376 S2P_Lmt13_Over_SOC3_24 "SOC过高3级告警阈值";
CM_ SG_ 2417356376 S2P_Lmt13_Over_DSOC_24 "SOC过高告警消除回差阈值";
CM_ SG_ 2417356377 S2P_Lmt13_Over_SOC1_25 "SOC过高1级告警阈值";
CM_ SG_ 2417356377 S2P_Lmt13_Over_SOC2_25 "SOC过高2级告警阈值";
CM_ SG_ 2417356377 S2P_Lmt13_Over_SOC3_25 "SOC过高3级告警阈值";
CM_ SG_ 2417356377 S2P_Lmt13_Over_DSOC_25 "SOC过高告警消除回差阈值";
CM_ SG_ 2417356378 S2P_Lmt13_Over_SOC1_26 "SOC过高1级告警阈值";
CM_ SG_ 2417356378 S2P_Lmt13_Over_SOC2_26 "SOC过高2级告警阈值";
CM_ SG_ 2417356378 S2P_Lmt13_Over_SOC3_26 "SOC过高3级告警阈值";
CM_ SG_ 2417356378 S2P_Lmt13_Over_DSOC_26 "SOC过高告警消除回差阈值";
CM_ SG_ 2417356379 S2P_Lmt13_Over_SOC1_27 "SOC过高1级告警阈值";
CM_ SG_ 2417356379 S2P_Lmt13_Over_SOC2_27 "SOC过高2级告警阈值";
CM_ SG_ 2417356379 S2P_Lmt13_Over_SOC3_27 "SOC过高3级告警阈值";
CM_ SG_ 2417356379 S2P_Lmt13_Over_DSOC_27 "SOC过高告警消除回差阈值";
CM_ SG_ 2417356380 S2P_Lmt13_Over_SOC1_28 "SOC过高1级告警阈值";
CM_ SG_ 2417356380 S2P_Lmt13_Over_SOC2_28 "SOC过高2级告警阈值";
CM_ SG_ 2417356380 S2P_Lmt13_Over_SOC3_28 "SOC过高3级告警阈值";
CM_ SG_ 2417356380 S2P_Lmt13_Over_DSOC_28 "SOC过高告警消除回差阈值";
CM_ SG_ 2417356381 S2P_Lmt13_Over_SOC1_29 "SOC过高1级告警阈值";
CM_ SG_ 2417356381 S2P_Lmt13_Over_SOC2_29 "SOC过高2级告警阈值";
CM_ SG_ 2417356381 S2P_Lmt13_Over_SOC3_29 "SOC过高3级告警阈值";
CM_ SG_ 2417356381 S2P_Lmt13_Over_DSOC_29 "SOC过高告警消除回差阈值";
CM_ SG_ 2417356382 S2P_Lmt13_Over_SOC1_30 "SOC过高1级告警阈值";
CM_ SG_ 2417356382 S2P_Lmt13_Over_SOC2_30 "SOC过高2级告警阈值";
CM_ SG_ 2417356382 S2P_Lmt13_Over_SOC3_30 "SOC过高3级告警阈值";
CM_ SG_ 2417356382 S2P_Lmt13_Over_DSOC_30 "SOC过高告警消除回差阈值";
CM_ SG_ 2417356383 S2P_Lmt13_Over_SOC1_31 "SOC过高1级告警阈值";
CM_ SG_ 2417356383 S2P_Lmt13_Over_SOC2_31 "SOC过高2级告警阈值";
CM_ SG_ 2417356383 S2P_Lmt13_Over_SOC3_31 "SOC过高3级告警阈值";
CM_ SG_ 2417356383 S2P_Lmt13_Over_DSOC_31 "SOC过高告警消除回差阈值";
CM_ SG_ 2417356384 S2P_Lmt13_Over_SOC1_32 "SOC过高1级告警阈值";
CM_ SG_ 2417356384 S2P_Lmt13_Over_SOC2_32 "SOC过高2级告警阈值";
CM_ SG_ 2417356384 S2P_Lmt13_Over_SOC3_32 "SOC过高3级告警阈值";
CM_ SG_ 2417356384 S2P_Lmt13_Over_DSOC_32 "SOC过高告警消除回差阈值";
CM_ SG_ 2417356385 S2P_Lmt13_Over_SOC1_33 "SOC过高1级告警阈值";
CM_ SG_ 2417356385 S2P_Lmt13_Over_SOC2_33 "SOC过高2级告警阈值";
CM_ SG_ 2417356385 S2P_Lmt13_Over_SOC3_33 "SOC过高3级告警阈值";
CM_ SG_ 2417356385 S2P_Lmt13_Over_DSOC_33 "SOC过高告警消除回差阈值";
CM_ SG_ 2417356386 S2P_Lmt13_Over_SOC1_34 "SOC过高1级告警阈值";
CM_ SG_ 2417356386 S2P_Lmt13_Over_SOC2_34 "SOC过高2级告警阈值";
CM_ SG_ 2417356386 S2P_Lmt13_Over_SOC3_34 "SOC过高3级告警阈值";
CM_ SG_ 2417356386 S2P_Lmt13_Over_DSOC_34 "SOC过高告警消除回差阈值";
CM_ SG_ 2417356387 S2P_Lmt13_Over_SOC1_35 "SOC过高1级告警阈值";
CM_ SG_ 2417356387 S2P_Lmt13_Over_SOC2_35 "SOC过高2级告警阈值";
CM_ SG_ 2417356387 S2P_Lmt13_Over_SOC3_35 "SOC过高3级告警阈值";
CM_ SG_ 2417356387 S2P_Lmt13_Over_DSOC_35 "SOC过高告警消除回差阈值";
CM_ SG_ 2417356388 S2P_Lmt13_Over_SOC1_36 "SOC过高1级告警阈值";
CM_ SG_ 2417356388 S2P_Lmt13_Over_SOC2_36 "SOC过高2级告警阈值";
CM_ SG_ 2417356388 S2P_Lmt13_Over_SOC3_36 "SOC过高3级告警阈值";
CM_ SG_ 2417356388 S2P_Lmt13_Over_DSOC_36 "SOC过高告警消除回差阈值";
CM_ SG_ 2417356389 S2P_Lmt13_Over_SOC1_37 "SOC过高1级告警阈值";
CM_ SG_ 2417356389 S2P_Lmt13_Over_SOC2_37 "SOC过高2级告警阈值";
CM_ SG_ 2417356389 S2P_Lmt13_Over_SOC3_37 "SOC过高3级告警阈值";
CM_ SG_ 2417356389 S2P_Lmt13_Over_DSOC_37 "SOC过高告警消除回差阈值";
CM_ SG_ 2417356390 S2P_Lmt13_Over_SOC1_38 "SOC过高1级告警阈值";
CM_ SG_ 2417356390 S2P_Lmt13_Over_SOC2_38 "SOC过高2级告警阈值";
CM_ SG_ 2417356390 S2P_Lmt13_Over_SOC3_38 "SOC过高3级告警阈值";
CM_ SG_ 2417356390 S2P_Lmt13_Over_DSOC_38 "SOC过高告警消除回差阈值";
CM_ SG_ 2417356391 S2P_Lmt13_Over_SOC1_39 "SOC过高1级告警阈值";
CM_ SG_ 2417356391 S2P_Lmt13_Over_SOC2_39 "SOC过高2级告警阈值";
CM_ SG_ 2417356391 S2P_Lmt13_Over_SOC3_39 "SOC过高3级告警阈值";
CM_ SG_ 2417356391 S2P_Lmt13_Over_DSOC_39 "SOC过高告警消除回差阈值";
CM_ SG_ 2417356392 S2P_Lmt13_Over_SOC1_40 "SOC过高1级告警阈值";
CM_ SG_ 2417356392 S2P_Lmt13_Over_SOC2_40 "SOC过高2级告警阈值";
CM_ SG_ 2417356392 S2P_Lmt13_Over_SOC3_40 "SOC过高3级告警阈值";
CM_ SG_ 2417356392 S2P_Lmt13_Over_DSOC_40 "SOC过高告警消除回差阈值";
CM_ SG_ 2417356393 S2P_Lmt13_Over_SOC1_41 "SOC过高1级告警阈值";
CM_ SG_ 2417356393 S2P_Lmt13_Over_SOC2_41 "SOC过高2级告警阈值";
CM_ SG_ 2417356393 S2P_Lmt13_Over_SOC3_41 "SOC过高3级告警阈值";
CM_ SG_ 2417356393 S2P_Lmt13_Over_DSOC_41 "SOC过高告警消除回差阈值";
CM_ SG_ 2417356394 S2P_Lmt13_Over_SOC1_42 "SOC过高1级告警阈值";
CM_ SG_ 2417356394 S2P_Lmt13_Over_SOC2_42 "SOC过高2级告警阈值";
CM_ SG_ 2417356394 S2P_Lmt13_Over_SOC3_42 "SOC过高3级告警阈值";
CM_ SG_ 2417356394 S2P_Lmt13_Over_DSOC_42 "SOC过高告警消除回差阈值";
CM_ SG_ 2417356395 S2P_Lmt13_Over_SOC1_43 "SOC过高1级告警阈值";
CM_ SG_ 2417356395 S2P_Lmt13_Over_SOC2_43 "SOC过高2级告警阈值";
CM_ SG_ 2417356395 S2P_Lmt13_Over_SOC3_43 "SOC过高3级告警阈值";
CM_ SG_ 2417356395 S2P_Lmt13_Over_DSOC_43 "SOC过高告警消除回差阈值";
CM_ SG_ 2417356396 S2P_Lmt13_Over_SOC1_44 "SOC过高1级告警阈值";
CM_ SG_ 2417356396 S2P_Lmt13_Over_SOC2_44 "SOC过高2级告警阈值";
CM_ SG_ 2417356396 S2P_Lmt13_Over_SOC3_44 "SOC过高3级告警阈值";
CM_ SG_ 2417356396 S2P_Lmt13_Over_DSOC_44 "SOC过高告警消除回差阈值";
CM_ SG_ 2417356397 S2P_Lmt13_Over_SOC1_45 "SOC过高1级告警阈值";
CM_ SG_ 2417356397 S2P_Lmt13_Over_SOC2_45 "SOC过高2级告警阈值";
CM_ SG_ 2417356397 S2P_Lmt13_Over_SOC3_45 "SOC过高3级告警阈值";
CM_ SG_ 2417356397 S2P_Lmt13_Over_DSOC_45 "SOC过高告警消除回差阈值";
CM_ SG_ 2417356398 S2P_Lmt13_Over_SOC1_46 "SOC过高1级告警阈值";
CM_ SG_ 2417356398 S2P_Lmt13_Over_SOC2_46 "SOC过高2级告警阈值";
CM_ SG_ 2417356398 S2P_Lmt13_Over_SOC3_46 "SOC过高3级告警阈值";
CM_ SG_ 2417356398 S2P_Lmt13_Over_DSOC_46 "SOC过高告警消除回差阈值";
CM_ SG_ 2417356399 S2P_Lmt13_Over_SOC1_47 "SOC过高1级告警阈值";
CM_ SG_ 2417356399 S2P_Lmt13_Over_SOC2_47 "SOC过高2级告警阈值";
CM_ SG_ 2417356399 S2P_Lmt13_Over_SOC3_47 "SOC过高3级告警阈值";
CM_ SG_ 2417356399 S2P_Lmt13_Over_DSOC_47 "SOC过高告警消除回差阈值";
CM_ SG_ 2417356400 S2P_Lmt13_Over_SOC1_48 "SOC过高1级告警阈值";
CM_ SG_ 2417356400 S2P_Lmt13_Over_SOC2_48 "SOC过高2级告警阈值";
CM_ SG_ 2417356400 S2P_Lmt13_Over_SOC3_48 "SOC过高3级告警阈值";
CM_ SG_ 2417356400 S2P_Lmt13_Over_DSOC_48 "SOC过高告警消除回差阈值";
CM_ SG_ 2417356401 S2P_Lmt13_Over_SOC1_49 "SOC过高1级告警阈值";
CM_ SG_ 2417356401 S2P_Lmt13_Over_SOC2_49 "SOC过高2级告警阈值";
CM_ SG_ 2417356401 S2P_Lmt13_Over_SOC3_49 "SOC过高3级告警阈值";
CM_ SG_ 2417356401 S2P_Lmt13_Over_DSOC_49 "SOC过高告警消除回差阈值";
CM_ SG_ 2417356402 S2P_Lmt13_Over_SOC1_50 "SOC过高1级告警阈值";
CM_ SG_ 2417356402 S2P_Lmt13_Over_SOC2_50 "SOC过高2级告警阈值";
CM_ SG_ 2417356402 S2P_Lmt13_Over_SOC3_50 "SOC过高3级告警阈值";
CM_ SG_ 2417356402 S2P_Lmt13_Over_DSOC_50 "SOC过高告警消除回差阈值";
CM_ SG_ 2417356403 S2P_Lmt13_Over_SOC1_51 "SOC过高1级告警阈值";
CM_ SG_ 2417356403 S2P_Lmt13_Over_SOC2_51 "SOC过高2级告警阈值";
CM_ SG_ 2417356403 S2P_Lmt13_Over_SOC3_51 "SOC过高3级告警阈值";
CM_ SG_ 2417356403 S2P_Lmt13_Over_DSOC_51 "SOC过高告警消除回差阈值";
CM_ SG_ 2417356404 S2P_Lmt13_Over_SOC1_52 "SOC过高1级告警阈值";
CM_ SG_ 2417356404 S2P_Lmt13_Over_SOC2_52 "SOC过高2级告警阈值";
CM_ SG_ 2417356404 S2P_Lmt13_Over_SOC3_52 "SOC过高3级告警阈值";
CM_ SG_ 2417356404 S2P_Lmt13_Over_DSOC_52 "SOC过高告警消除回差阈值";
CM_ SG_ 2417356405 S2P_Lmt13_Over_SOC1_53 "SOC过高1级告警阈值";
CM_ SG_ 2417356405 S2P_Lmt13_Over_SOC2_53 "SOC过高2级告警阈值";
CM_ SG_ 2417356405 S2P_Lmt13_Over_SOC3_53 "SOC过高3级告警阈值";
CM_ SG_ 2417356405 S2P_Lmt13_Over_DSOC_53 "SOC过高告警消除回差阈值";
CM_ SG_ 2417356406 S2P_Lmt13_Over_SOC1_54 "SOC过高1级告警阈值";
CM_ SG_ 2417356406 S2P_Lmt13_Over_SOC2_54 "SOC过高2级告警阈值";
CM_ SG_ 2417356406 S2P_Lmt13_Over_SOC3_54 "SOC过高3级告警阈值";
CM_ SG_ 2417356406 S2P_Lmt13_Over_DSOC_54 "SOC过高告警消除回差阈值";
CM_ SG_ 2417356407 S2P_Lmt13_Over_SOC1_55 "SOC过高1级告警阈值";
CM_ SG_ 2417356407 S2P_Lmt13_Over_SOC2_55 "SOC过高2级告警阈值";
CM_ SG_ 2417356407 S2P_Lmt13_Over_SOC3_55 "SOC过高3级告警阈值";
CM_ SG_ 2417356407 S2P_Lmt13_Over_DSOC_55 "SOC过高告警消除回差阈值";
CM_ SG_ 2417356408 S2P_Lmt13_Over_SOC1_56 "SOC过高1级告警阈值";
CM_ SG_ 2417356408 S2P_Lmt13_Over_SOC2_56 "SOC过高2级告警阈值";
CM_ SG_ 2417356408 S2P_Lmt13_Over_SOC3_56 "SOC过高3级告警阈值";
CM_ SG_ 2417356408 S2P_Lmt13_Over_DSOC_56 "SOC过高告警消除回差阈值";
CM_ SG_ 2417356409 S2P_Lmt13_Over_SOC1_57 "SOC过高1级告警阈值";
CM_ SG_ 2417356409 S2P_Lmt13_Over_SOC2_57 "SOC过高2级告警阈值";
CM_ SG_ 2417356409 S2P_Lmt13_Over_SOC3_57 "SOC过高3级告警阈值";
CM_ SG_ 2417356409 S2P_Lmt13_Over_DSOC_57 "SOC过高告警消除回差阈值";
CM_ SG_ 2417356410 S2P_Lmt13_Over_SOC1_58 "SOC过高1级告警阈值";
CM_ SG_ 2417356410 S2P_Lmt13_Over_SOC2_58 "SOC过高2级告警阈值";
CM_ SG_ 2417356410 S2P_Lmt13_Over_SOC3_58 "SOC过高3级告警阈值";
CM_ SG_ 2417356410 S2P_Lmt13_Over_DSOC_58 "SOC过高告警消除回差阈值";
CM_ SG_ 2417356411 S2P_Lmt13_Over_SOC1_59 "SOC过高1级告警阈值";
CM_ SG_ 2417356411 S2P_Lmt13_Over_SOC2_59 "SOC过高2级告警阈值";
CM_ SG_ 2417356411 S2P_Lmt13_Over_SOC3_59 "SOC过高3级告警阈值";
CM_ SG_ 2417356411 S2P_Lmt13_Over_DSOC_59 "SOC过高告警消除回差阈值";
CM_ SG_ 2417356412 S2P_Lmt13_Over_SOC1_60 "SOC过高1级告警阈值";
CM_ SG_ 2417356412 S2P_Lmt13_Over_SOC2_60 "SOC过高2级告警阈值";
CM_ SG_ 2417356412 S2P_Lmt13_Over_SOC3_60 "SOC过高3级告警阈值";
CM_ SG_ 2417356412 S2P_Lmt13_Over_DSOC_60 "SOC过高告警消除回差阈值";
CM_ SG_ 2417356413 S2P_Lmt13_Over_SOC1_61 "SOC过高1级告警阈值";
CM_ SG_ 2417356413 S2P_Lmt13_Over_SOC2_61 "SOC过高2级告警阈值";
CM_ SG_ 2417356413 S2P_Lmt13_Over_SOC3_61 "SOC过高3级告警阈值";
CM_ SG_ 2417356413 S2P_Lmt13_Over_DSOC_61 "SOC过高告警消除回差阈值";
CM_ SG_ 2417356414 S2P_Lmt13_Over_SOC1_62 "SOC过高1级告警阈值";
CM_ SG_ 2417356414 S2P_Lmt13_Over_SOC2_62 "SOC过高2级告警阈值";
CM_ SG_ 2417356414 S2P_Lmt13_Over_SOC3_62 "SOC过高3级告警阈值";
CM_ SG_ 2417356414 S2P_Lmt13_Over_DSOC_62 "SOC过高告警消除回差阈值";
CM_ SG_ 2417356415 S2P_Lmt13_Over_SOC1_63 "SOC过高1级告警阈值";
CM_ SG_ 2417356415 S2P_Lmt13_Over_SOC2_63 "SOC过高2级告警阈值";
CM_ SG_ 2417356415 S2P_Lmt13_Over_SOC3_63 "SOC过高3级告警阈值";
CM_ SG_ 2417356415 S2P_Lmt13_Over_DSOC_63 "SOC过高告警消除回差阈值";
CM_ SG_ 2417421889 S2P_Lmt14_Under_SOC1_01 "SOC过低1级告警阈值";
CM_ SG_ 2417421889 S2P_Lmt14_Under_SOC2_01 "SOC过低2级告警阈值";
CM_ SG_ 2417421889 S2P_Lmt14_Under_SOC3_01 "SOC过低3级告警阈值";
CM_ SG_ 2417421889 S2P_Lmt14_Under_DSOC_01 "SOC过低告警消除回差阈值";
CM_ SG_ 2417421890 S2P_Lmt14_Under_SOC1_02 "SOC过低1级告警阈值";
CM_ SG_ 2417421890 S2P_Lmt14_Under_SOC2_02 "SOC过低2级告警阈值";
CM_ SG_ 2417421890 S2P_Lmt14_Under_SOC3_02 "SOC过低3级告警阈值";
CM_ SG_ 2417421890 S2P_Lmt14_Under_DSOC_02 "SOC过低告警消除回差阈值";
CM_ SG_ 2417421891 S2P_Lmt14_Under_SOC1_03 "SOC过低1级告警阈值";
CM_ SG_ 2417421891 S2P_Lmt14_Under_SOC2_03 "SOC过低2级告警阈值";
CM_ SG_ 2417421891 S2P_Lmt14_Under_SOC3_03 "SOC过低3级告警阈值";
CM_ SG_ 2417421891 S2P_Lmt14_Under_DSOC_03 "SOC过低告警消除回差阈值";
CM_ SG_ 2417421892 S2P_Lmt14_Under_SOC1_04 "SOC过低1级告警阈值";
CM_ SG_ 2417421892 S2P_Lmt14_Under_SOC2_04 "SOC过低2级告警阈值";
CM_ SG_ 2417421892 S2P_Lmt14_Under_SOC3_04 "SOC过低3级告警阈值";
CM_ SG_ 2417421892 S2P_Lmt14_Under_DSOC_04 "SOC过低告警消除回差阈值";
CM_ SG_ 2417421893 S2P_Lmt14_Under_SOC1_05 "SOC过低1级告警阈值";
CM_ SG_ 2417421893 S2P_Lmt14_Under_SOC2_05 "SOC过低2级告警阈值";
CM_ SG_ 2417421893 S2P_Lmt14_Under_SOC3_05 "SOC过低3级告警阈值";
CM_ SG_ 2417421893 S2P_Lmt14_Under_DSOC_05 "SOC过低告警消除回差阈值";
CM_ SG_ 2417421894 S2P_Lmt14_Under_SOC1_06 "SOC过低1级告警阈值";
CM_ SG_ 2417421894 S2P_Lmt14_Under_SOC2_06 "SOC过低2级告警阈值";
CM_ SG_ 2417421894 S2P_Lmt14_Under_SOC3_06 "SOC过低3级告警阈值";
CM_ SG_ 2417421894 S2P_Lmt14_Under_DSOC_06 "SOC过低告警消除回差阈值";
CM_ SG_ 2417421895 S2P_Lmt14_Under_SOC1_07 "SOC过低1级告警阈值";
CM_ SG_ 2417421895 S2P_Lmt14_Under_SOC2_07 "SOC过低2级告警阈值";
CM_ SG_ 2417421895 S2P_Lmt14_Under_SOC3_07 "SOC过低3级告警阈值";
CM_ SG_ 2417421895 S2P_Lmt14_Under_DSOC_07 "SOC过低告警消除回差阈值";
CM_ SG_ 2417421896 S2P_Lmt14_Under_SOC1_08 "SOC过低1级告警阈值";
CM_ SG_ 2417421896 S2P_Lmt14_Under_SOC2_08 "SOC过低2级告警阈值";
CM_ SG_ 2417421896 S2P_Lmt14_Under_SOC3_08 "SOC过低3级告警阈值";
CM_ SG_ 2417421896 S2P_Lmt14_Under_DSOC_08 "SOC过低告警消除回差阈值";
CM_ SG_ 2417421897 S2P_Lmt14_Under_SOC1_09 "SOC过低1级告警阈值";
CM_ SG_ 2417421897 S2P_Lmt14_Under_SOC2_09 "SOC过低2级告警阈值";
CM_ SG_ 2417421897 S2P_Lmt14_Under_SOC3_09 "SOC过低3级告警阈值";
CM_ SG_ 2417421897 S2P_Lmt14_Under_DSOC_09 "SOC过低告警消除回差阈值";
CM_ SG_ 2417421898 S2P_Lmt14_Under_SOC1_10 "SOC过低1级告警阈值";
CM_ SG_ 2417421898 S2P_Lmt14_Under_SOC2_10 "SOC过低2级告警阈值";
CM_ SG_ 2417421898 S2P_Lmt14_Under_SOC3_10 "SOC过低3级告警阈值";
CM_ SG_ 2417421898 S2P_Lmt14_Under_DSOC_10 "SOC过低告警消除回差阈值";
CM_ SG_ 2417421899 S2P_Lmt14_Under_SOC1_11 "SOC过低1级告警阈值";
CM_ SG_ 2417421899 S2P_Lmt14_Under_SOC2_11 "SOC过低2级告警阈值";
CM_ SG_ 2417421899 S2P_Lmt14_Under_SOC3_11 "SOC过低3级告警阈值";
CM_ SG_ 2417421899 S2P_Lmt14_Under_DSOC_11 "SOC过低告警消除回差阈值";
CM_ SG_ 2417421900 S2P_Lmt14_Under_SOC1_12 "SOC过低1级告警阈值";
CM_ SG_ 2417421900 S2P_Lmt14_Under_SOC2_12 "SOC过低2级告警阈值";
CM_ SG_ 2417421900 S2P_Lmt14_Under_SOC3_12 "SOC过低3级告警阈值";
CM_ SG_ 2417421900 S2P_Lmt14_Under_DSOC_12 "SOC过低告警消除回差阈值";
CM_ SG_ 2417421901 S2P_Lmt14_Under_SOC1_13 "SOC过低1级告警阈值";
CM_ SG_ 2417421901 S2P_Lmt14_Under_SOC2_13 "SOC过低2级告警阈值";
CM_ SG_ 2417421901 S2P_Lmt14_Under_SOC3_13 "SOC过低3级告警阈值";
CM_ SG_ 2417421901 S2P_Lmt14_Under_DSOC_13 "SOC过低告警消除回差阈值";
CM_ SG_ 2417421902 S2P_Lmt14_Under_SOC1_14 "SOC过低1级告警阈值";
CM_ SG_ 2417421902 S2P_Lmt14_Under_SOC2_14 "SOC过低2级告警阈值";
CM_ SG_ 2417421902 S2P_Lmt14_Under_SOC3_14 "SOC过低3级告警阈值";
CM_ SG_ 2417421902 S2P_Lmt14_Under_DSOC_14 "SOC过低告警消除回差阈值";
CM_ SG_ 2417421903 S2P_Lmt14_Under_SOC1_15 "SOC过低1级告警阈值";
CM_ SG_ 2417421903 S2P_Lmt14_Under_SOC2_15 "SOC过低2级告警阈值";
CM_ SG_ 2417421903 S2P_Lmt14_Under_SOC3_15 "SOC过低3级告警阈值";
CM_ SG_ 2417421903 S2P_Lmt14_Under_DSOC_15 "SOC过低告警消除回差阈值";
CM_ SG_ 2417421904 S2P_Lmt14_Under_SOC1_16 "SOC过低1级告警阈值";
CM_ SG_ 2417421904 S2P_Lmt14_Under_SOC2_16 "SOC过低2级告警阈值";
CM_ SG_ 2417421904 S2P_Lmt14_Under_SOC3_16 "SOC过低3级告警阈值";
CM_ SG_ 2417421904 S2P_Lmt14_Under_DSOC_16 "SOC过低告警消除回差阈值";
CM_ SG_ 2417421905 S2P_Lmt14_Under_SOC1_17 "SOC过低1级告警阈值";
CM_ SG_ 2417421905 S2P_Lmt14_Under_SOC2_17 "SOC过低2级告警阈值";
CM_ SG_ 2417421905 S2P_Lmt14_Under_SOC3_17 "SOC过低3级告警阈值";
CM_ SG_ 2417421905 S2P_Lmt14_Under_DSOC_17 "SOC过低告警消除回差阈值";
CM_ SG_ 2417421906 S2P_Lmt14_Under_SOC1_18 "SOC过低1级告警阈值";
CM_ SG_ 2417421906 S2P_Lmt14_Under_SOC2_18 "SOC过低2级告警阈值";
CM_ SG_ 2417421906 S2P_Lmt14_Under_SOC3_18 "SOC过低3级告警阈值";
CM_ SG_ 2417421906 S2P_Lmt14_Under_DSOC_18 "SOC过低告警消除回差阈值";
CM_ SG_ 2417421907 S2P_Lmt14_Under_SOC1_19 "SOC过低1级告警阈值";
CM_ SG_ 2417421907 S2P_Lmt14_Under_SOC2_19 "SOC过低2级告警阈值";
CM_ SG_ 2417421907 S2P_Lmt14_Under_SOC3_19 "SOC过低3级告警阈值";
CM_ SG_ 2417421907 S2P_Lmt14_Under_DSOC_19 "SOC过低告警消除回差阈值";
CM_ SG_ 2417421908 S2P_Lmt14_Under_SOC1_20 "SOC过低1级告警阈值";
CM_ SG_ 2417421908 S2P_Lmt14_Under_SOC2_20 "SOC过低2级告警阈值";
CM_ SG_ 2417421908 S2P_Lmt14_Under_SOC3_20 "SOC过低3级告警阈值";
CM_ SG_ 2417421908 S2P_Lmt14_Under_DSOC_20 "SOC过低告警消除回差阈值";
CM_ SG_ 2417421909 S2P_Lmt14_Under_SOC1_21 "SOC过低1级告警阈值";
CM_ SG_ 2417421909 S2P_Lmt14_Under_SOC2_21 "SOC过低2级告警阈值";
CM_ SG_ 2417421909 S2P_Lmt14_Under_SOC3_21 "SOC过低3级告警阈值";
CM_ SG_ 2417421909 S2P_Lmt14_Under_DSOC_21 "SOC过低告警消除回差阈值";
CM_ SG_ 2417421910 S2P_Lmt14_Under_SOC1_22 "SOC过低1级告警阈值";
CM_ SG_ 2417421910 S2P_Lmt14_Under_SOC2_22 "SOC过低2级告警阈值";
CM_ SG_ 2417421910 S2P_Lmt14_Under_SOC3_22 "SOC过低3级告警阈值";
CM_ SG_ 2417421910 S2P_Lmt14_Under_DSOC_22 "SOC过低告警消除回差阈值";
CM_ SG_ 2417421911 S2P_Lmt14_Under_SOC1_23 "SOC过低1级告警阈值";
CM_ SG_ 2417421911 S2P_Lmt14_Under_SOC2_23 "SOC过低2级告警阈值";
CM_ SG_ 2417421911 S2P_Lmt14_Under_SOC3_23 "SOC过低3级告警阈值";
CM_ SG_ 2417421911 S2P_Lmt14_Under_DSOC_23 "SOC过低告警消除回差阈值";
CM_ SG_ 2417421912 S2P_Lmt14_Under_SOC1_24 "SOC过低1级告警阈值";
CM_ SG_ 2417421912 S2P_Lmt14_Under_SOC2_24 "SOC过低2级告警阈值";
CM_ SG_ 2417421912 S2P_Lmt14_Under_SOC3_24 "SOC过低3级告警阈值";
CM_ SG_ 2417421912 S2P_Lmt14_Under_DSOC_24 "SOC过低告警消除回差阈值";
CM_ SG_ 2417421913 S2P_Lmt14_Under_SOC1_25 "SOC过低1级告警阈值";
CM_ SG_ 2417421913 S2P_Lmt14_Under_SOC2_25 "SOC过低2级告警阈值";
CM_ SG_ 2417421913 S2P_Lmt14_Under_SOC3_25 "SOC过低3级告警阈值";
CM_ SG_ 2417421913 S2P_Lmt14_Under_DSOC_25 "SOC过低告警消除回差阈值";
CM_ SG_ 2417421914 S2P_Lmt14_Under_SOC1_26 "SOC过低1级告警阈值";
CM_ SG_ 2417421914 S2P_Lmt14_Under_SOC2_26 "SOC过低2级告警阈值";
CM_ SG_ 2417421914 S2P_Lmt14_Under_SOC3_26 "SOC过低3级告警阈值";
CM_ SG_ 2417421914 S2P_Lmt14_Under_DSOC_26 "SOC过低告警消除回差阈值";
CM_ SG_ 2417421915 S2P_Lmt14_Under_SOC1_27 "SOC过低1级告警阈值";
CM_ SG_ 2417421915 S2P_Lmt14_Under_SOC2_27 "SOC过低2级告警阈值";
CM_ SG_ 2417421915 S2P_Lmt14_Under_SOC3_27 "SOC过低3级告警阈值";
CM_ SG_ 2417421915 S2P_Lmt14_Under_DSOC_27 "SOC过低告警消除回差阈值";
CM_ SG_ 2417421916 S2P_Lmt14_Under_SOC1_28 "SOC过低1级告警阈值";
CM_ SG_ 2417421916 S2P_Lmt14_Under_SOC2_28 "SOC过低2级告警阈值";
CM_ SG_ 2417421916 S2P_Lmt14_Under_SOC3_28 "SOC过低3级告警阈值";
CM_ SG_ 2417421916 S2P_Lmt14_Under_DSOC_28 "SOC过低告警消除回差阈值";
CM_ SG_ 2417421917 S2P_Lmt14_Under_SOC1_29 "SOC过低1级告警阈值";
CM_ SG_ 2417421917 S2P_Lmt14_Under_SOC2_29 "SOC过低2级告警阈值";
CM_ SG_ 2417421917 S2P_Lmt14_Under_SOC3_29 "SOC过低3级告警阈值";
CM_ SG_ 2417421917 S2P_Lmt14_Under_DSOC_29 "SOC过低告警消除回差阈值";
CM_ SG_ 2417421918 S2P_Lmt14_Under_SOC1_30 "SOC过低1级告警阈值";
CM_ SG_ 2417421918 S2P_Lmt14_Under_SOC2_30 "SOC过低2级告警阈值";
CM_ SG_ 2417421918 S2P_Lmt14_Under_SOC3_30 "SOC过低3级告警阈值";
CM_ SG_ 2417421918 S2P_Lmt14_Under_DSOC_30 "SOC过低告警消除回差阈值";
CM_ SG_ 2417421919 S2P_Lmt14_Under_SOC1_31 "SOC过低1级告警阈值";
CM_ SG_ 2417421919 S2P_Lmt14_Under_SOC2_31 "SOC过低2级告警阈值";
CM_ SG_ 2417421919 S2P_Lmt14_Under_SOC3_31 "SOC过低3级告警阈值";
CM_ SG_ 2417421919 S2P_Lmt14_Under_DSOC_31 "SOC过低告警消除回差阈值";
CM_ SG_ 2417421920 S2P_Lmt14_Under_SOC1_32 "SOC过低1级告警阈值";
CM_ SG_ 2417421920 S2P_Lmt14_Under_SOC2_32 "SOC过低2级告警阈值";
CM_ SG_ 2417421920 S2P_Lmt14_Under_SOC3_32 "SOC过低3级告警阈值";
CM_ SG_ 2417421920 S2P_Lmt14_Under_DSOC_32 "SOC过低告警消除回差阈值";
CM_ SG_ 2417421921 S2P_Lmt14_Under_SOC1_33 "SOC过低1级告警阈值";
CM_ SG_ 2417421921 S2P_Lmt14_Under_SOC2_33 "SOC过低2级告警阈值";
CM_ SG_ 2417421921 S2P_Lmt14_Under_SOC3_33 "SOC过低3级告警阈值";
CM_ SG_ 2417421921 S2P_Lmt14_Under_DSOC_33 "SOC过低告警消除回差阈值";
CM_ SG_ 2417421922 S2P_Lmt14_Under_SOC1_34 "SOC过低1级告警阈值";
CM_ SG_ 2417421922 S2P_Lmt14_Under_SOC2_34 "SOC过低2级告警阈值";
CM_ SG_ 2417421922 S2P_Lmt14_Under_SOC3_34 "SOC过低3级告警阈值";
CM_ SG_ 2417421922 S2P_Lmt14_Under_DSOC_34 "SOC过低告警消除回差阈值";
CM_ SG_ 2417421923 S2P_Lmt14_Under_SOC1_35 "SOC过低1级告警阈值";
CM_ SG_ 2417421923 S2P_Lmt14_Under_SOC2_35 "SOC过低2级告警阈值";
CM_ SG_ 2417421923 S2P_Lmt14_Under_SOC3_35 "SOC过低3级告警阈值";
CM_ SG_ 2417421923 S2P_Lmt14_Under_DSOC_35 "SOC过低告警消除回差阈值";
CM_ SG_ 2417421924 S2P_Lmt14_Under_SOC1_36 "SOC过低1级告警阈值";
CM_ SG_ 2417421924 S2P_Lmt14_Under_SOC2_36 "SOC过低2级告警阈值";
CM_ SG_ 2417421924 S2P_Lmt14_Under_SOC3_36 "SOC过低3级告警阈值";
CM_ SG_ 2417421924 S2P_Lmt14_Under_DSOC_36 "SOC过低告警消除回差阈值";
CM_ SG_ 2417421925 S2P_Lmt14_Under_SOC1_37 "SOC过低1级告警阈值";
CM_ SG_ 2417421925 S2P_Lmt14_Under_SOC2_37 "SOC过低2级告警阈值";
CM_ SG_ 2417421925 S2P_Lmt14_Under_SOC3_37 "SOC过低3级告警阈值";
CM_ SG_ 2417421925 S2P_Lmt14_Under_DSOC_37 "SOC过低告警消除回差阈值";
CM_ SG_ 2417421926 S2P_Lmt14_Under_SOC1_38 "SOC过低1级告警阈值";
CM_ SG_ 2417421926 S2P_Lmt14_Under_SOC2_38 "SOC过低2级告警阈值";
CM_ SG_ 2417421926 S2P_Lmt14_Under_SOC3_38 "SOC过低3级告警阈值";
CM_ SG_ 2417421926 S2P_Lmt14_Under_DSOC_38 "SOC过低告警消除回差阈值";
CM_ SG_ 2417421927 S2P_Lmt14_Under_SOC1_39 "SOC过低1级告警阈值";
CM_ SG_ 2417421927 S2P_Lmt14_Under_SOC2_39 "SOC过低2级告警阈值";
CM_ SG_ 2417421927 S2P_Lmt14_Under_SOC3_39 "SOC过低3级告警阈值";
CM_ SG_ 2417421927 S2P_Lmt14_Under_DSOC_39 "SOC过低告警消除回差阈值";
CM_ SG_ 2417421928 S2P_Lmt14_Under_SOC1_40 "SOC过低1级告警阈值";
CM_ SG_ 2417421928 S2P_Lmt14_Under_SOC2_40 "SOC过低2级告警阈值";
CM_ SG_ 2417421928 S2P_Lmt14_Under_SOC3_40 "SOC过低3级告警阈值";
CM_ SG_ 2417421928 S2P_Lmt14_Under_DSOC_40 "SOC过低告警消除回差阈值";
CM_ SG_ 2417421929 S2P_Lmt14_Under_SOC1_41 "SOC过低1级告警阈值";
CM_ SG_ 2417421929 S2P_Lmt14_Under_SOC2_41 "SOC过低2级告警阈值";
CM_ SG_ 2417421929 S2P_Lmt14_Under_SOC3_41 "SOC过低3级告警阈值";
CM_ SG_ 2417421929 S2P_Lmt14_Under_DSOC_41 "SOC过低告警消除回差阈值";
CM_ SG_ 2417421930 S2P_Lmt14_Under_SOC1_42 "SOC过低1级告警阈值";
CM_ SG_ 2417421930 S2P_Lmt14_Under_SOC2_42 "SOC过低2级告警阈值";
CM_ SG_ 2417421930 S2P_Lmt14_Under_SOC3_42 "SOC过低3级告警阈值";
CM_ SG_ 2417421930 S2P_Lmt14_Under_DSOC_42 "SOC过低告警消除回差阈值";
CM_ SG_ 2417421931 S2P_Lmt14_Under_SOC1_43 "SOC过低1级告警阈值";
CM_ SG_ 2417421931 S2P_Lmt14_Under_SOC2_43 "SOC过低2级告警阈值";
CM_ SG_ 2417421931 S2P_Lmt14_Under_SOC3_43 "SOC过低3级告警阈值";
CM_ SG_ 2417421931 S2P_Lmt14_Under_DSOC_43 "SOC过低告警消除回差阈值";
CM_ SG_ 2417421932 S2P_Lmt14_Under_SOC1_44 "SOC过低1级告警阈值";
CM_ SG_ 2417421932 S2P_Lmt14_Under_SOC2_44 "SOC过低2级告警阈值";
CM_ SG_ 2417421932 S2P_Lmt14_Under_SOC3_44 "SOC过低3级告警阈值";
CM_ SG_ 2417421932 S2P_Lmt14_Under_DSOC_44 "SOC过低告警消除回差阈值";
CM_ SG_ 2417421933 S2P_Lmt14_Under_SOC1_45 "SOC过低1级告警阈值";
CM_ SG_ 2417421933 S2P_Lmt14_Under_SOC2_45 "SOC过低2级告警阈值";
CM_ SG_ 2417421933 S2P_Lmt14_Under_SOC3_45 "SOC过低3级告警阈值";
CM_ SG_ 2417421933 S2P_Lmt14_Under_DSOC_45 "SOC过低告警消除回差阈值";
CM_ SG_ 2417421934 S2P_Lmt14_Under_SOC1_46 "SOC过低1级告警阈值";
CM_ SG_ 2417421934 S2P_Lmt14_Under_SOC2_46 "SOC过低2级告警阈值";
CM_ SG_ 2417421934 S2P_Lmt14_Under_SOC3_46 "SOC过低3级告警阈值";
CM_ SG_ 2417421934 S2P_Lmt14_Under_DSOC_46 "SOC过低告警消除回差阈值";
CM_ SG_ 2417421935 S2P_Lmt14_Under_SOC1_47 "SOC过低1级告警阈值";
CM_ SG_ 2417421935 S2P_Lmt14_Under_SOC2_47 "SOC过低2级告警阈值";
CM_ SG_ 2417421935 S2P_Lmt14_Under_SOC3_47 "SOC过低3级告警阈值";
CM_ SG_ 2417421935 S2P_Lmt14_Under_DSOC_47 "SOC过低告警消除回差阈值";
CM_ SG_ 2417421936 S2P_Lmt14_Under_SOC1_48 "SOC过低1级告警阈值";
CM_ SG_ 2417421936 S2P_Lmt14_Under_SOC2_48 "SOC过低2级告警阈值";
CM_ SG_ 2417421936 S2P_Lmt14_Under_SOC3_48 "SOC过低3级告警阈值";
CM_ SG_ 2417421936 S2P_Lmt14_Under_DSOC_48 "SOC过低告警消除回差阈值";
CM_ SG_ 2417421937 S2P_Lmt14_Under_SOC1_49 "SOC过低1级告警阈值";
CM_ SG_ 2417421937 S2P_Lmt14_Under_SOC2_49 "SOC过低2级告警阈值";
CM_ SG_ 2417421937 S2P_Lmt14_Under_SOC3_49 "SOC过低3级告警阈值";
CM_ SG_ 2417421937 S2P_Lmt14_Under_DSOC_49 "SOC过低告警消除回差阈值";
CM_ SG_ 2417421938 S2P_Lmt14_Under_SOC1_50 "SOC过低1级告警阈值";
CM_ SG_ 2417421938 S2P_Lmt14_Under_SOC2_50 "SOC过低2级告警阈值";
CM_ SG_ 2417421938 S2P_Lmt14_Under_SOC3_50 "SOC过低3级告警阈值";
CM_ SG_ 2417421938 S2P_Lmt14_Under_DSOC_50 "SOC过低告警消除回差阈值";
CM_ SG_ 2417421939 S2P_Lmt14_Under_SOC1_51 "SOC过低1级告警阈值";
CM_ SG_ 2417421939 S2P_Lmt14_Under_SOC2_51 "SOC过低2级告警阈值";
CM_ SG_ 2417421939 S2P_Lmt14_Under_SOC3_51 "SOC过低3级告警阈值";
CM_ SG_ 2417421939 S2P_Lmt14_Under_DSOC_51 "SOC过低告警消除回差阈值";
CM_ SG_ 2417421940 S2P_Lmt14_Under_SOC1_52 "SOC过低1级告警阈值";
CM_ SG_ 2417421940 S2P_Lmt14_Under_SOC2_52 "SOC过低2级告警阈值";
CM_ SG_ 2417421940 S2P_Lmt14_Under_SOC3_52 "SOC过低3级告警阈值";
CM_ SG_ 2417421940 S2P_Lmt14_Under_DSOC_52 "SOC过低告警消除回差阈值";
CM_ SG_ 2417421941 S2P_Lmt14_Under_SOC1_53 "SOC过低1级告警阈值";
CM_ SG_ 2417421941 S2P_Lmt14_Under_SOC2_53 "SOC过低2级告警阈值";
CM_ SG_ 2417421941 S2P_Lmt14_Under_SOC3_53 "SOC过低3级告警阈值";
CM_ SG_ 2417421941 S2P_Lmt14_Under_DSOC_53 "SOC过低告警消除回差阈值";
CM_ SG_ 2417421942 S2P_Lmt14_Under_SOC1_54 "SOC过低1级告警阈值";
CM_ SG_ 2417421942 S2P_Lmt14_Under_SOC2_54 "SOC过低2级告警阈值";
CM_ SG_ 2417421942 S2P_Lmt14_Under_SOC3_54 "SOC过低3级告警阈值";
CM_ SG_ 2417421942 S2P_Lmt14_Under_DSOC_54 "SOC过低告警消除回差阈值";
CM_ SG_ 2417421943 S2P_Lmt14_Under_SOC1_55 "SOC过低1级告警阈值";
CM_ SG_ 2417421943 S2P_Lmt14_Under_SOC2_55 "SOC过低2级告警阈值";
CM_ SG_ 2417421943 S2P_Lmt14_Under_SOC3_55 "SOC过低3级告警阈值";
CM_ SG_ 2417421943 S2P_Lmt14_Under_DSOC_55 "SOC过低告警消除回差阈值";
CM_ SG_ 2417421944 S2P_Lmt14_Under_SOC1_56 "SOC过低1级告警阈值";
CM_ SG_ 2417421944 S2P_Lmt14_Under_SOC2_56 "SOC过低2级告警阈值";
CM_ SG_ 2417421944 S2P_Lmt14_Under_SOC3_56 "SOC过低3级告警阈值";
CM_ SG_ 2417421944 S2P_Lmt14_Under_DSOC_56 "SOC过低告警消除回差阈值";
CM_ SG_ 2417421945 S2P_Lmt14_Under_SOC1_57 "SOC过低1级告警阈值";
CM_ SG_ 2417421945 S2P_Lmt14_Under_SOC2_57 "SOC过低2级告警阈值";
CM_ SG_ 2417421945 S2P_Lmt14_Under_SOC3_57 "SOC过低3级告警阈值";
CM_ SG_ 2417421945 S2P_Lmt14_Under_DSOC_57 "SOC过低告警消除回差阈值";
CM_ SG_ 2417421946 S2P_Lmt14_Under_SOC1_58 "SOC过低1级告警阈值";
CM_ SG_ 2417421946 S2P_Lmt14_Under_SOC2_58 "SOC过低2级告警阈值";
CM_ SG_ 2417421946 S2P_Lmt14_Under_SOC3_58 "SOC过低3级告警阈值";
CM_ SG_ 2417421946 S2P_Lmt14_Under_DSOC_58 "SOC过低告警消除回差阈值";
CM_ SG_ 2417421947 S2P_Lmt14_Under_SOC1_59 "SOC过低1级告警阈值";
CM_ SG_ 2417421947 S2P_Lmt14_Under_SOC2_59 "SOC过低2级告警阈值";
CM_ SG_ 2417421947 S2P_Lmt14_Under_SOC3_59 "SOC过低3级告警阈值";
CM_ SG_ 2417421947 S2P_Lmt14_Under_DSOC_59 "SOC过低告警消除回差阈值";
CM_ SG_ 2417421948 S2P_Lmt14_Under_SOC1_60 "SOC过低1级告警阈值";
CM_ SG_ 2417421948 S2P_Lmt14_Under_SOC2_60 "SOC过低2级告警阈值";
CM_ SG_ 2417421948 S2P_Lmt14_Under_SOC3_60 "SOC过低3级告警阈值";
CM_ SG_ 2417421948 S2P_Lmt14_Under_DSOC_60 "SOC过低告警消除回差阈值";
CM_ SG_ 2417421949 S2P_Lmt14_Under_SOC1_61 "SOC过低1级告警阈值";
CM_ SG_ 2417421949 S2P_Lmt14_Under_SOC2_61 "SOC过低2级告警阈值";
CM_ SG_ 2417421949 S2P_Lmt14_Under_SOC3_61 "SOC过低3级告警阈值";
CM_ SG_ 2417421949 S2P_Lmt14_Under_DSOC_61 "SOC过低告警消除回差阈值";
CM_ SG_ 2417421950 S2P_Lmt14_Under_SOC1_62 "SOC过低1级告警阈值";
CM_ SG_ 2417421950 S2P_Lmt14_Under_SOC2_62 "SOC过低2级告警阈值";
CM_ SG_ 2417421950 S2P_Lmt14_Under_SOC3_62 "SOC过低3级告警阈值";
CM_ SG_ 2417421950 S2P_Lmt14_Under_DSOC_62 "SOC过低告警消除回差阈值";
CM_ SG_ 2417421951 S2P_Lmt14_Under_SOC1_63 "SOC过低1级告警阈值";
CM_ SG_ 2417421951 S2P_Lmt14_Under_SOC2_63 "SOC过低2级告警阈值";
CM_ SG_ 2417421951 S2P_Lmt14_Under_SOC3_63 "SOC过低3级告警阈值";
CM_ SG_ 2417421951 S2P_Lmt14_Under_DSOC_63 "SOC过低告警消除回差阈值";
CM_ SG_ 2197352447 S2P_VerData_Data0 "CSC发送ETH的软件版本号报文字节1（实际没有发送）";
CM_ SG_ 2197352447 S2P_VerData_Data1 "CSC发送ETH的软件版本号报文字节2（实际没有发送）";
CM_ SG_ 2197352447 S2P_VerData_Data2 "CSC发送ETH的软件版本号报文字节3（实际没有发送）";
CM_ SG_ 2197352447 S2P_VerData_Data3 "CSC发送ETH的软件版本号报文字节4（实际没有发送）";
CM_ SG_ 2197352447 S2P_VerData_Data4 "CSC发送ETH的软件版本号报文字节5（实际没有发送）";
CM_ SG_ 2197352447 S2P_VerData_Data5 "CSC发送ETH的软件版本号报文字节6（实际没有发送）";
CM_ SG_ 2197352447 S2P_VerData_Data6 "CSC发送ETH的软件版本号报文字节7（实际没有发送）";
CM_ SG_ 2197352447 S2P_VerData_Data7 "CSC发送ETH的软件版本号报文字节8（实际没有发送）";
CM_ SG_ 2197680127 S2P_WriteOK_Data0 "发送页数写入确认数据帧报文字节1";
CM_ SG_ 2197680127 S2P_WriteOK_Data1 "发送页数写入确认数据帧报文字节2";
CM_ SG_ 2197680127 S2P_WriteOK_Data2 "发送页数写入确认数据帧报文字节3";
CM_ SG_ 2197680127 S2P_WriteOK_Data3 "发送页数写入确认数据帧报文字节4";
CM_ SG_ 2197680127 S2P_WriteOK_Data4 "发送页数写入确认数据帧报文字节5";
CM_ SG_ 2197680127 S2P_WriteOK_Data5 "发送页数写入确认数据帧报文字节6";
CM_ SG_ 2197680127 S2P_WriteOK_Data6 "发送页数写入确认数据帧报文字节7";
CM_ SG_ 2197680127 S2P_WriteOK_Data7 "发送页数写入确认数据帧报文字节8";
CM_ SG_ 2197352193 S2P_CSCVerData_Data0_01 "CSC发送的软件版本号报文字节1";
CM_ SG_ 2197352193 S2P_CSCVerData_Data1_01 "CSC发送的软件版本号报文字节2";
CM_ SG_ 2197352193 S2P_CSCVerData_Data2_01 "CSC发送的软件版本号报文字节3";
CM_ SG_ 2197352193 S2P_CSCVerData_Data3_01 "CSC发送的软件版本号报文字节4";
CM_ SG_ 2197352193 S2P_CSCVerData_Data4_01 "CSC发送的软件版本号报文字节5";
CM_ SG_ 2197352193 S2P_CSCVerData_Data5_01 "CSC发送的软件版本号报文字节6";
CM_ SG_ 2197352193 S2P_CSCVerData_Data6_01 "CSC发送的软件版本号报文字节7";
CM_ SG_ 2197352193 S2P_CSCVerData_Data7_01 "CSC发送的软件版本号报文字节8";
CM_ SG_ 2197352194 S2P_CSCVerData_Data0_02 "CSC发送的软件版本号报文字节1";
CM_ SG_ 2197352194 S2P_CSCVerData_Data1_02 "CSC发送的软件版本号报文字节2";
CM_ SG_ 2197352194 S2P_CSCVerData_Data2_02 "CSC发送的软件版本号报文字节3";
CM_ SG_ 2197352194 S2P_CSCVerData_Data3_02 "CSC发送的软件版本号报文字节4";
CM_ SG_ 2197352194 S2P_CSCVerData_Data4_02 "CSC发送的软件版本号报文字节5";
CM_ SG_ 2197352194 S2P_CSCVerData_Data5_02 "CSC发送的软件版本号报文字节6";
CM_ SG_ 2197352194 S2P_CSCVerData_Data6_02 "CSC发送的软件版本号报文字节7";
CM_ SG_ 2197352194 S2P_CSCVerData_Data7_02 "CSC发送的软件版本号报文字节8";
CM_ SG_ 2197352195 S2P_CSCVerData_Data0_03 "CSC发送的软件版本号报文字节1";
CM_ SG_ 2197352195 S2P_CSCVerData_Data1_03 "CSC发送的软件版本号报文字节2";
CM_ SG_ 2197352195 S2P_CSCVerData_Data2_03 "CSC发送的软件版本号报文字节3";
CM_ SG_ 2197352195 S2P_CSCVerData_Data3_03 "CSC发送的软件版本号报文字节4";
CM_ SG_ 2197352195 S2P_CSCVerData_Data4_03 "CSC发送的软件版本号报文字节5";
CM_ SG_ 2197352195 S2P_CSCVerData_Data5_03 "CSC发送的软件版本号报文字节6";
CM_ SG_ 2197352195 S2P_CSCVerData_Data6_03 "CSC发送的软件版本号报文字节7";
CM_ SG_ 2197352195 S2P_CSCVerData_Data7_03 "CSC发送的软件版本号报文字节8";
CM_ SG_ 2197352196 S2P_CSCVerData_Data0_04 "CSC发送的软件版本号报文字节1";
CM_ SG_ 2197352196 S2P_CSCVerData_Data1_04 "CSC发送的软件版本号报文字节2";
CM_ SG_ 2197352196 S2P_CSCVerData_Data2_04 "CSC发送的软件版本号报文字节3";
CM_ SG_ 2197352196 S2P_CSCVerData_Data3_04 "CSC发送的软件版本号报文字节4";
CM_ SG_ 2197352196 S2P_CSCVerData_Data4_04 "CSC发送的软件版本号报文字节5";
CM_ SG_ 2197352196 S2P_CSCVerData_Data5_04 "CSC发送的软件版本号报文字节6";
CM_ SG_ 2197352196 S2P_CSCVerData_Data6_04 "CSC发送的软件版本号报文字节7";
CM_ SG_ 2197352196 S2P_CSCVerData_Data7_04 "CSC发送的软件版本号报文字节8";
CM_ SG_ 2197352197 S2P_CSCVerData_Data0_05 "CSC发送的软件版本号报文字节1";
CM_ SG_ 2197352197 S2P_CSCVerData_Data1_05 "CSC发送的软件版本号报文字节2";
CM_ SG_ 2197352197 S2P_CSCVerData_Data2_05 "CSC发送的软件版本号报文字节3";
CM_ SG_ 2197352197 S2P_CSCVerData_Data3_05 "CSC发送的软件版本号报文字节4";
CM_ SG_ 2197352197 S2P_CSCVerData_Data4_05 "CSC发送的软件版本号报文字节5";
CM_ SG_ 2197352197 S2P_CSCVerData_Data5_05 "CSC发送的软件版本号报文字节6";
CM_ SG_ 2197352197 S2P_CSCVerData_Data6_05 "CSC发送的软件版本号报文字节7";
CM_ SG_ 2197352197 S2P_CSCVerData_Data7_05 "CSC发送的软件版本号报文字节8";
VERSION ""

NS_ :

BS_:

BU_: MBMU PC SBMU IMM ETH DCDC LEMS

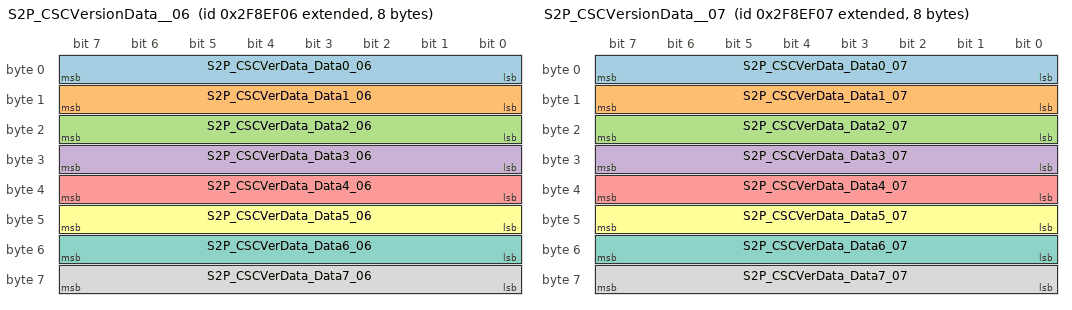
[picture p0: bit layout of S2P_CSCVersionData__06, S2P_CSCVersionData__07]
BO_ 2197352198 S2P_CSCVersionData__06: 8 SBMU
 SG_ S2P_CSCVerData_Data0_06 : 0|8@1+ (1,0) [0|255] "%"  PC
 SG_ S2P_CSCVerData_Data1_06 : 8|8@1+ (1,0) [0|255] "%"  PC
 SG_ S2P_CSCVerData_Data2_06 : 16|8@1+ (1,0) [0|255] "%"  PC
 SG_ S2P_CSCVerData_Data3_06 : 24|8@1+ (1,0) [0|255] "%"  PC
 SG_ S2P_CSCVerData_Data4_06 : 32|8@1+ (1,0) [0|255] "%"  PC
 SG_ S2P_CSCVerData_Data5_06 : 40|8@1+ (1,0) [0|255] "%"  PC
 SG_ S2P_CSCVerData_Data6_06 : 48|8@1+ (1,0) [0|255] "%"  PC
 SG_ S2P_CSCVerData_Data7_06 : 56|8@1+ (1,0) [0|255] "%"  PC

BO_ 2197352199 S2P_CSCVersionData__07: 8 SBMU
 SG_ S2P_CSCVerData_Data0_07 : 0|8@1+ (1,0) [0|255] "%"  PC
 SG_ S2P_CSCVerData_Data1_07 : 8|8@1+ (1,0) [0|255] "%"  PC
 SG_ S2P_CSCVerData_Data2_07 : 16|8@1+ (1,0) [0|255] "%"  PC
 SG_ S2P_CSCVerData_Data3_07 : 24|8@1+ (1,0) [0|255] "%"  PC
 SG_ S2P_CSCVerData_Data4_07 : 32|8@1+ (1,0) [0|255] "%"  PC
 SG_ S2P_CSCVerData_Data5_07 : 40|8@1+ (1,0) [0|255] "%"  PC
 SG_ S2P_CSCVerData_Data6_07 : 48|8@1+ (1,0) [0|255] "%"  PC
 SG_ S2P_CSCVerData_Data7_07 : 56|8@1+ (1,0) [0|255] "%"  PC

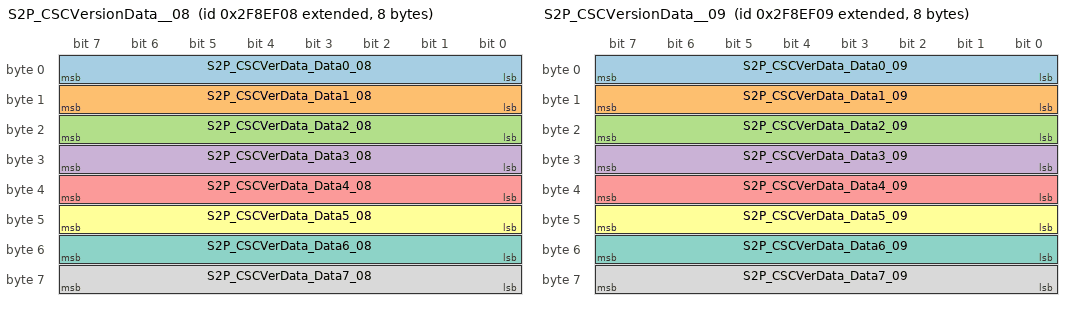
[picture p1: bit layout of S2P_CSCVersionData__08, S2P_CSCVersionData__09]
BO_ 2197352200 S2P_CSCVersionData__08: 8 SBMU
 SG_ S2P_CSCVerData_Data0_08 : 0|8@1+ (1,0) [0|255] "%"  PC
 SG_ S2P_CSCVerData_Data1_08 : 8|8@1+ (1,0) [0|255] "%"  PC
 SG_ S2P_CSCVerData_Data2_08 : 16|8@1+ (1,0) [0|255] "%"  PC
 SG_ S2P_CSCVerData_Data3_08 : 24|8@1+ (1,0) [0|255] "%"  PC
 SG_ S2P_CSCVerData_Data4_08 : 32|8@1+ (1,0) [0|255] "%"  PC
 SG_ S2P_CSCVerData_Data5_08 : 40|8@1+ (1,0) [0|255] "%"  PC
 SG_ S2P_CSCVerData_Data6_08 : 48|8@1+ (1,0) [0|255] "%"  PC
 SG_ S2P_CSCVerData_Data7_08 : 56|8@1+ (1,0) [0|255] "%"  PC

BO_ 2197352201 S2P_CSCVersionData__09: 8 SBMU
 SG_ S2P_CSCVerData_Data0_09 : 0|8@1+ (1,0) [0|255] "%"  PC
 SG_ S2P_CSCVerData_Data1_09 : 8|8@1+ (1,0) [0|255] "%"  PC
 SG_ S2P_CSCVerData_Data2_09 : 16|8@1+ (1,0) [0|255] "%"  PC
 SG_ S2P_CSCVerData_Data3_09 : 24|8@1+ (1,0) [0|255] "%"  PC
 SG_ S2P_CSCVerData_Data4_09 : 32|8@1+ (1,0) [0|255] "%"  PC
 SG_ S2P_CSCVerData_Data5_09 : 40|8@1+ (1,0) [0|255] "%"  PC
 SG_ S2P_CSCVerData_Data6_09 : 48|8@1+ (1,0) [0|255] "%"  PC
 SG_ S2P_CSCVerData_Data7_09 : 56|8@1+ (1,0) [0|255] "%"  PC

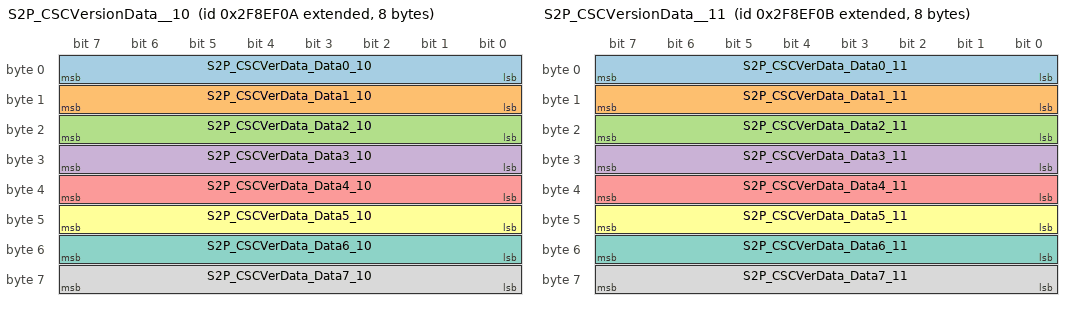
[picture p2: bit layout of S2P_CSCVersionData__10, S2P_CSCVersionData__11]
BO_ 2197352202 S2P_CSCVersionData__10: 8 SBMU
 SG_ S2P_CSCVerData_Data0_10 : 0|8@1+ (1,0) [0|255] "%"  PC
 SG_ S2P_CSCVerData_Data1_10 : 8|8@1+ (1,0) [0|255] "%"  PC
 SG_ S2P_CSCVerData_Data2_10 : 16|8@1+ (1,0) [0|255] "%"  PC
 SG_ S2P_CSCVerData_Data3_10 : 24|8@1+ (1,0) [0|255] "%"  PC
 SG_ S2P_CSCVerData_Data4_10 : 32|8@1+ (1,0) [0|255] "%"  PC
 SG_ S2P_CSCVerData_Data5_10 : 40|8@1+ (1,0) [0|255] "%"  PC
 SG_ S2P_CSCVerData_Data6_10 : 48|8@1+ (1,0) [0|255] "%"  PC
 SG_ S2P_CSCVerData_Data7_10 : 56|8@1+ (1,0) [0|255] "%"  PC

BO_ 2197352203 S2P_CSCVersionData__11: 8 SBMU
 SG_ S2P_CSCVerData_Data0_11 : 0|8@1+ (1,0) [0|255] "%"  PC
 SG_ S2P_CSCVerData_Data1_11 : 8|8@1+ (1,0) [0|255] "%"  PC
 SG_ S2P_CSCVerData_Data2_11 : 16|8@1+ (1,0) [0|255] "%"  PC
 SG_ S2P_CSCVerData_Data3_11 : 24|8@1+ (1,0) [0|255] "%"  PC
 SG_ S2P_CSCVerData_Data4_11 : 32|8@1+ (1,0) [0|255] "%"  PC
 SG_ S2P_CSCVerData_Data5_11 : 40|8@1+ (1,0) [0|255] "%"  PC
 SG_ S2P_CSCVerData_Data6_11 : 48|8@1+ (1,0) [0|255] "%"  PC
 SG_ S2P_CSCVerData_Data7_11 : 56|8@1+ (1,0) [0|255] "%"  PC

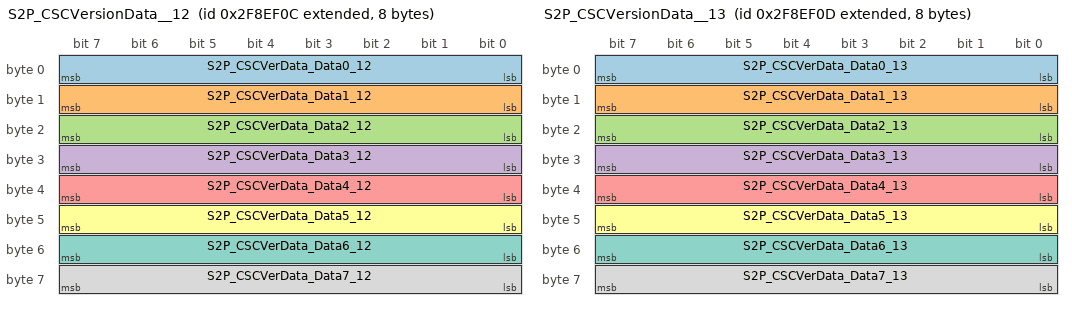
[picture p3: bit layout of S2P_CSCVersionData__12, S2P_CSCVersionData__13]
BO_ 2197352204 S2P_CSCVersionData__12: 8 SBMU
 SG_ S2P_CSCVerData_Data0_12 : 0|8@1+ (1,0) [0|255] "%"  PC
 SG_ S2P_CSCVerData_Data1_12 : 8|8@1+ (1,0) [0|255] "%"  PC
 SG_ S2P_CSCVerData_Data2_12 : 16|8@1+ (1,0) [0|255] "%"  PC
 SG_ S2P_CSCVerData_Data3_12 : 24|8@1+ (1,0) [0|255] "%"  PC
 SG_ S2P_CSCVerData_Data4_12 : 32|8@1+ (1,0) [0|255] "%"  PC
 SG_ S2P_CSCVerData_Data5_12 : 40|8@1+ (1,0) [0|255] "%"  PC
 SG_ S2P_CSCVerData_Data6_12 : 48|8@1+ (1,0) [0|255] "%"  PC
 SG_ S2P_CSCVerData_Data7_12 : 56|8@1+ (1,0) [0|255] "%"  PC

BO_ 2197352205 S2P_CSCVersionData__13: 8 SBMU
 SG_ S2P_CSCVerData_Data0_13 : 0|8@1+ (1,0) [0|255] "%"  PC
 SG_ S2P_CSCVerData_Data1_13 : 8|8@1+ (1,0) [0|255] "%"  PC
 SG_ S2P_CSCVerData_Data2_13 : 16|8@1+ (1,0) [0|255] "%"  PC
 SG_ S2P_CSCVerData_Data3_13 : 24|8@1+ (1,0) [0|255] "%"  PC
 SG_ S2P_CSCVerData_Data4_13 : 32|8@1+ (1,0) [0|255] "%"  PC
 SG_ S2P_CSCVerData_Data5_13 : 40|8@1+ (1,0) [0|255] "%"  PC
 SG_ S2P_CSCVerData_Data6_13 : 48|8@1+ (1,0) [0|255] "%"  PC
 SG_ S2P_CSCVerData_Data7_13 : 56|8@1+ (1,0) [0|255] "%"  PC

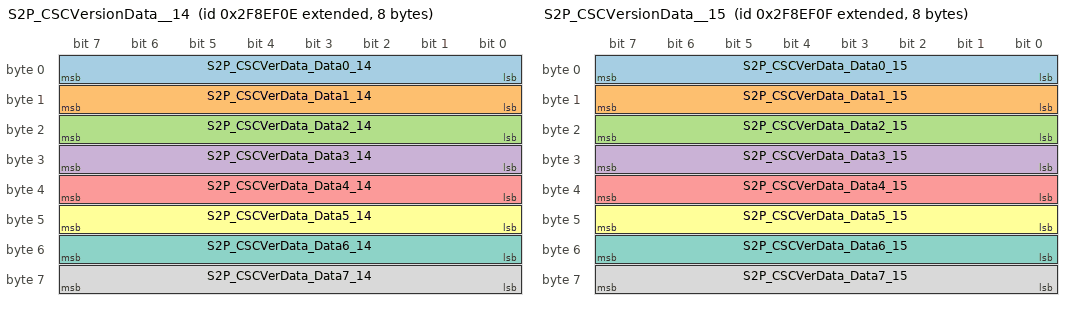
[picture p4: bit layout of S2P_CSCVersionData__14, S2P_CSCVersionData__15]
BO_ 2197352206 S2P_CSCVersionData__14: 8 SBMU
 SG_ S2P_CSCVerData_Data0_14 : 0|8@1+ (1,0) [0|255] "%"  PC
 SG_ S2P_CSCVerData_Data1_14 : 8|8@1+ (1,0) [0|255] "%"  PC
 SG_ S2P_CSCVerData_Data2_14 : 16|8@1+ (1,0) [0|255] "%"  PC
 SG_ S2P_CSCVerData_Data3_14 : 24|8@1+ (1,0) [0|255] "%"  PC
 SG_ S2P_CSCVerData_Data4_14 : 32|8@1+ (1,0) [0|255] "%"  PC
 SG_ S2P_CSCVerData_Data5_14 : 40|8@1+ (1,0) [0|255] "%"  PC
 SG_ S2P_CSCVerData_Data6_14 : 48|8@1+ (1,0) [0|255] "%"  PC
 SG_ S2P_CSCVerData_Data7_14 : 56|8@1+ (1,0) [0|255] "%"  PC

BO_ 2197352207 S2P_CSCVersionData__15: 8 SBMU
 SG_ S2P_CSCVerData_Data0_15 : 0|8@1+ (1,0) [0|255] "%"  PC
 SG_ S2P_CSCVerData_Data1_15 : 8|8@1+ (1,0) [0|255] "%"  PC
 SG_ S2P_CSCVerData_Data2_15 : 16|8@1+ (1,0) [0|255] "%"  PC
 SG_ S2P_CSCVerData_Data3_15 : 24|8@1+ (1,0) [0|255] "%"  PC
 SG_ S2P_CSCVerData_Data4_15 : 32|8@1+ (1,0) [0|255] "%"  PC
 SG_ S2P_CSCVerData_Data5_15 : 40|8@1+ (1,0) [0|255] "%"  PC
 SG_ S2P_CSCVerData_Data6_15 : 48|8@1+ (1,0) [0|255] "%"  PC
 SG_ S2P_CSCVerData_Data7_15 : 56|8@1+ (1,0) [0|255] "%"  PC

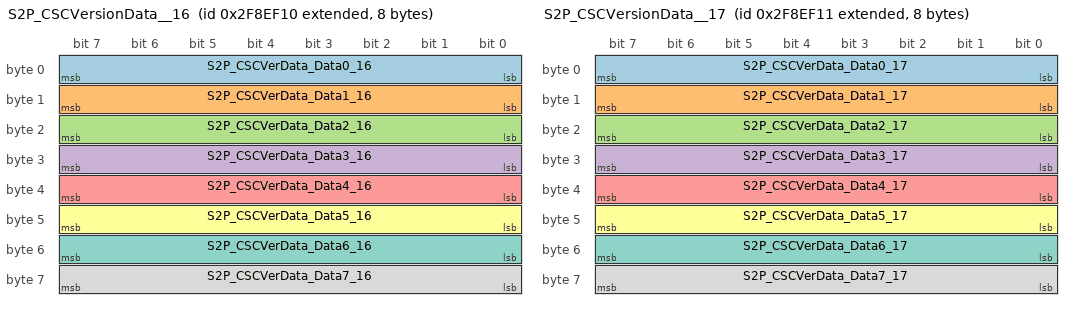
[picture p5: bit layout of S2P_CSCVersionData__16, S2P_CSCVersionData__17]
BO_ 2197352208 S2P_CSCVersionData__16: 8 SBMU
 SG_ S2P_CSCVerData_Data0_16 : 0|8@1+ (1,0) [0|255] "%"  PC
 SG_ S2P_CSCVerData_Data1_16 : 8|8@1+ (1,0) [0|255] "%"  PC
 SG_ S2P_CSCVerData_Data2_16 : 16|8@1+ (1,0) [0|255] "%"  PC
 SG_ S2P_CSCVerData_Data3_16 : 24|8@1+ (1,0) [0|255] "%"  PC
 SG_ S2P_CSCVerData_Data4_16 : 32|8@1+ (1,0) [0|255] "%"  PC
 SG_ S2P_CSCVerData_Data5_16 : 40|8@1+ (1,0) [0|255] "%"  PC
 SG_ S2P_CSCVerData_Data6_16 : 48|8@1+ (1,0) [0|255] "%"  PC
 SG_ S2P_CSCVerData_Data7_16 : 56|8@1+ (1,0) [0|255] "%"  PC

BO_ 2197352209 S2P_CSCVersionData__17: 8 SBMU
 SG_ S2P_CSCVerData_Data0_17 : 0|8@1+ (1,0) [0|255] "%"  PC
 SG_ S2P_CSCVerData_Data1_17 : 8|8@1+ (1,0) [0|255] "%"  PC
 SG_ S2P_CSCVerData_Data2_17 : 16|8@1+ (1,0) [0|255] "%"  PC
 SG_ S2P_CSCVerData_Data3_17 : 24|8@1+ (1,0) [0|255] "%"  PC
 SG_ S2P_CSCVerData_Data4_17 : 32|8@1+ (1,0) [0|255] "%"  PC
 SG_ S2P_CSCVerData_Data5_17 : 40|8@1+ (1,0) [0|255] "%"  PC
 SG_ S2P_CSCVerData_Data6_17 : 48|8@1+ (1,0) [0|255] "%"  PC
 SG_ S2P_CSCVerData_Data7_17 : 56|8@1+ (1,0) [0|255] "%"  PC

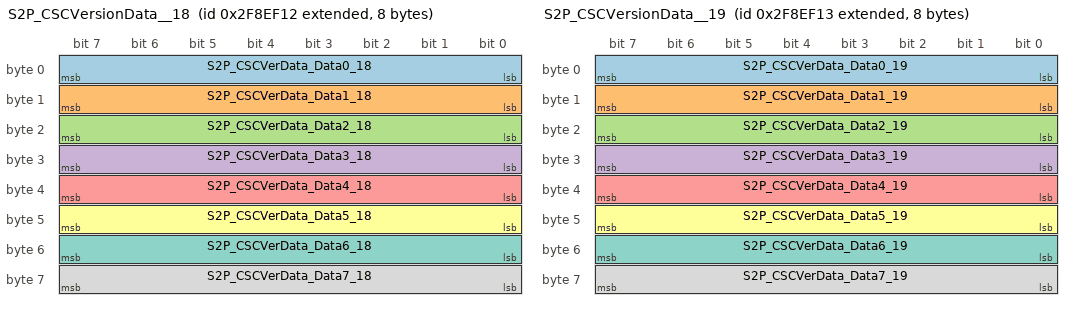
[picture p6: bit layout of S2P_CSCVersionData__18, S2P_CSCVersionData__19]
BO_ 2197352210 S2P_CSCVersionData__18: 8 SBMU
 SG_ S2P_CSCVerData_Data0_18 : 0|8@1+ (1,0) [0|255] "%"  PC
 SG_ S2P_CSCVerData_Data1_18 : 8|8@1+ (1,0) [0|255] "%"  PC
 SG_ S2P_CSCVerData_Data2_18 : 16|8@1+ (1,0) [0|255] "%"  PC
 SG_ S2P_CSCVerData_Data3_18 : 24|8@1+ (1,0) [0|255] "%"  PC
 SG_ S2P_CSCVerData_Data4_18 : 32|8@1+ (1,0) [0|255] "%"  PC
 SG_ S2P_CSCVerData_Data5_18 : 40|8@1+ (1,0) [0|255] "%"  PC
 SG_ S2P_CSCVerData_Data6_18 : 48|8@1+ (1,0) [0|255] "%"  PC
 SG_ S2P_CSCVerData_Data7_18 : 56|8@1+ (1,0) [0|255] "%"  PC

BO_ 2197352211 S2P_CSCVersionData__19: 8 SBMU
 SG_ S2P_CSCVerData_Data0_19 : 0|8@1+ (1,0) [0|255] "%"  PC
 SG_ S2P_CSCVerData_Data1_19 : 8|8@1+ (1,0) [0|255] "%"  PC
 SG_ S2P_CSCVerData_Data2_19 : 16|8@1+ (1,0) [0|255] "%"  PC
 SG_ S2P_CSCVerData_Data3_19 : 24|8@1+ (1,0) [0|255] "%"  PC
 SG_ S2P_CSCVerData_Data4_19 : 32|8@1+ (1,0) [0|255] "%"  PC
 SG_ S2P_CSCVerData_Data5_19 : 40|8@1+ (1,0) [0|255] "%"  PC
 SG_ S2P_CSCVerData_Data6_19 : 48|8@1+ (1,0) [0|255] "%"  PC
 SG_ S2P_CSCVerData_Data7_19 : 56|8@1+ (1,0) [0|255] "%"  PC

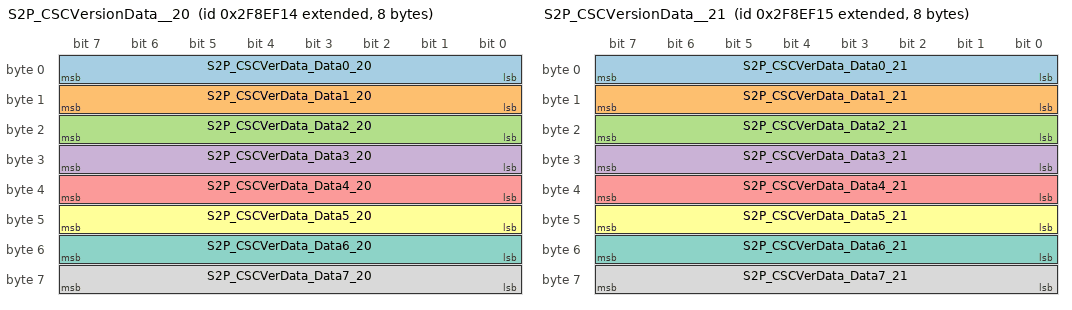
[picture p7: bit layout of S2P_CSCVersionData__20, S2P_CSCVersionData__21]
BO_ 2197352212 S2P_CSCVersionData__20: 8 SBMU
 SG_ S2P_CSCVerData_Data0_20 : 0|8@1+ (1,0) [0|255] "%"  PC
 SG_ S2P_CSCVerData_Data1_20 : 8|8@1+ (1,0) [0|255] "%"  PC
 SG_ S2P_CSCVerData_Data2_20 : 16|8@1+ (1,0) [0|255] "%"  PC
 SG_ S2P_CSCVerData_Data3_20 : 24|8@1+ (1,0) [0|255] "%"  PC
 SG_ S2P_CSCVerData_Data4_20 : 32|8@1+ (1,0) [0|255] "%"  PC
 SG_ S2P_CSCVerData_Data5_20 : 40|8@1+ (1,0) [0|255] "%"  PC
 SG_ S2P_CSCVerData_Data6_20 : 48|8@1+ (1,0) [0|255] "%"  PC
 SG_ S2P_CSCVerData_Data7_20 : 56|8@1+ (1,0) [0|255] "%"  PC

BO_ 2197352213 S2P_CSCVersionData__21: 8 SBMU
 SG_ S2P_CSCVerData_Data0_21 : 0|8@1+ (1,0) [0|255] "%"  PC
 SG_ S2P_CSCVerData_Data1_21 : 8|8@1+ (1,0) [0|255] "%"  PC
 SG_ S2P_CSCVerData_Data2_21 : 16|8@1+ (1,0) [0|255] "%"  PC
 SG_ S2P_CSCVerData_Data3_21 : 24|8@1+ (1,0) [0|255] "%"  PC
 SG_ S2P_CSCVerData_Data4_21 : 32|8@1+ (1,0) [0|255] "%"  PC
 SG_ S2P_CSCVerData_Data5_21 : 40|8@1+ (1,0) [0|255] "%"  PC
 SG_ S2P_CSCVerData_Data6_21 : 48|8@1+ (1,0) [0|255] "%"  PC
 SG_ S2P_CSCVerData_Data7_21 : 56|8@1+ (1,0) [0|255] "%"  PC

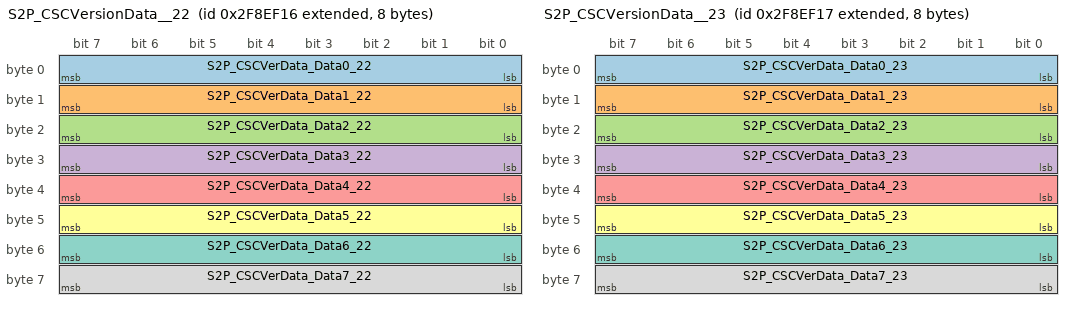
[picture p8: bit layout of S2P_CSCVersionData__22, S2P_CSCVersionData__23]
BO_ 2197352214 S2P_CSCVersionData__22: 8 SBMU
 SG_ S2P_CSCVerData_Data0_22 : 0|8@1+ (1,0) [0|255] "%"  PC
 SG_ S2P_CSCVerData_Data1_22 : 8|8@1+ (1,0) [0|255] "%"  PC
 SG_ S2P_CSCVerData_Data2_22 : 16|8@1+ (1,0) [0|255] "%"  PC
 SG_ S2P_CSCVerData_Data3_22 : 24|8@1+ (1,0) [0|255] "%"  PC
 SG_ S2P_CSCVerData_Data4_22 : 32|8@1+ (1,0) [0|255] "%"  PC
 SG_ S2P_CSCVerData_Data5_22 : 40|8@1+ (1,0) [0|255] "%"  PC
 SG_ S2P_CSCVerData_Data6_22 : 48|8@1+ (1,0) [0|255] "%"  PC
 SG_ S2P_CSCVerData_Data7_22 : 56|8@1+ (1,0) [0|255] "%"  PC

BO_ 2197352215 S2P_CSCVersionData__23: 8 SBMU
 SG_ S2P_CSCVerData_Data0_23 : 0|8@1+ (1,0) [0|255] "%"  PC
 SG_ S2P_CSCVerData_Data1_23 : 8|8@1+ (1,0) [0|255] "%"  PC
 SG_ S2P_CSCVerData_Data2_23 : 16|8@1+ (1,0) [0|255] "%"  PC
 SG_ S2P_CSCVerData_Data3_23 : 24|8@1+ (1,0) [0|255] "%"  PC
 SG_ S2P_CSCVerData_Data4_23 : 32|8@1+ (1,0) [0|255] "%"  PC
 SG_ S2P_CSCVerData_Data5_23 : 40|8@1+ (1,0) [0|255] "%"  PC
 SG_ S2P_CSCVerData_Data6_23 : 48|8@1+ (1,0) [0|255] "%"  PC
 SG_ S2P_CSCVerData_Data7_23 : 56|8@1+ (1,0) [0|255] "%"  PC

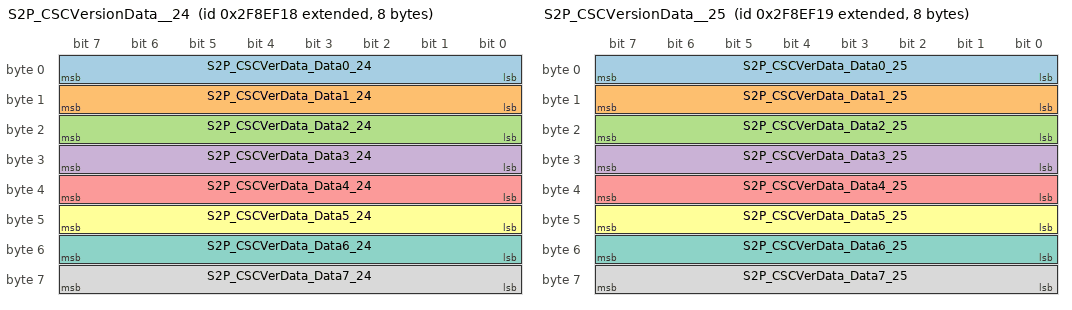
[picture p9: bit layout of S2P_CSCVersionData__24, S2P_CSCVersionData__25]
BO_ 2197352216 S2P_CSCVersionData__24: 8 SBMU
 SG_ S2P_CSCVerData_Data0_24 : 0|8@1+ (1,0) [0|255] "%"  PC
 SG_ S2P_CSCVerData_Data1_24 : 8|8@1+ (1,0) [0|255] "%"  PC
 SG_ S2P_CSCVerData_Data2_24 : 16|8@1+ (1,0) [0|255] "%"  PC
 SG_ S2P_CSCVerData_Data3_24 : 24|8@1+ (1,0) [0|255] "%"  PC
 SG_ S2P_CSCVerData_Data4_24 : 32|8@1+ (1,0) [0|255] "%"  PC
 SG_ S2P_CSCVerData_Data5_24 : 40|8@1+ (1,0) [0|255] "%"  PC
 SG_ S2P_CSCVerData_Data6_24 : 48|8@1+ (1,0) [0|255] "%"  PC
 SG_ S2P_CSCVerData_Data7_24 : 56|8@1+ (1,0) [0|255] "%"  PC

BO_ 2197352217 S2P_CSCVersionData__25: 8 SBMU
 SG_ S2P_CSCVerData_Data0_25 : 0|8@1+ (1,0) [0|255] "%"  PC
 SG_ S2P_CSCVerData_Data1_25 : 8|8@1+ (1,0) [0|255] "%"  PC
 SG_ S2P_CSCVerData_Data2_25 : 16|8@1+ (1,0) [0|255] "%"  PC
 SG_ S2P_CSCVerData_Data3_25 : 24|8@1+ (1,0) [0|255] "%"  PC
 SG_ S2P_CSCVerData_Data4_25 : 32|8@1+ (1,0) [0|255] "%"  PC
 SG_ S2P_CSCVerData_Data5_25 : 40|8@1+ (1,0) [0|255] "%"  PC
 SG_ S2P_CSCVerData_Data6_25 : 48|8@1+ (1,0) [0|255] "%"  PC
 SG_ S2P_CSCVerData_Data7_25 : 56|8@1+ (1,0) [0|255] "%"  PC

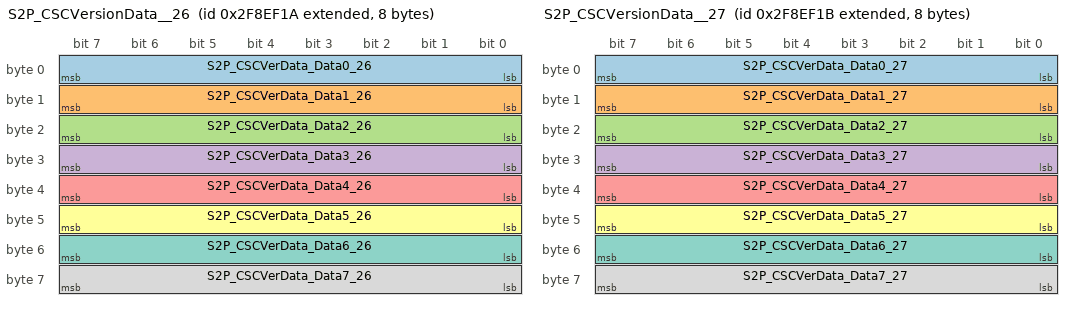
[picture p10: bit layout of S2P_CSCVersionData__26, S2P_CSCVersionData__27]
BO_ 2197352218 S2P_CSCVersionData__26: 8 SBMU
 SG_ S2P_CSCVerData_Data0_26 : 0|8@1+ (1,0) [0|255] "%"  PC
 SG_ S2P_CSCVerData_Data1_26 : 8|8@1+ (1,0) [0|255] "%"  PC
 SG_ S2P_CSCVerData_Data2_26 : 16|8@1+ (1,0) [0|255] "%"  PC
 SG_ S2P_CSCVerData_Data3_26 : 24|8@1+ (1,0) [0|255] "%"  PC
 SG_ S2P_CSCVerData_Data4_26 : 32|8@1+ (1,0) [0|255] "%"  PC
 SG_ S2P_CSCVerData_Data5_26 : 40|8@1+ (1,0) [0|255] "%"  PC
 SG_ S2P_CSCVerData_Data6_26 : 48|8@1+ (1,0) [0|255] "%"  PC
 SG_ S2P_CSCVerData_Data7_26 : 56|8@1+ (1,0) [0|255] "%"  PC

BO_ 2197352219 S2P_CSCVersionData__27: 8 SBMU
 SG_ S2P_CSCVerData_Data0_27 : 0|8@1+ (1,0) [0|255] "%"  PC
 SG_ S2P_CSCVerData_Data1_27 : 8|8@1+ (1,0) [0|255] "%"  PC
 SG_ S2P_CSCVerData_Data2_27 : 16|8@1+ (1,0) [0|255] "%"  PC
 SG_ S2P_CSCVerData_Data3_27 : 24|8@1+ (1,0) [0|255] "%"  PC
 SG_ S2P_CSCVerData_Data4_27 : 32|8@1+ (1,0) [0|255] "%"  PC
 SG_ S2P_CSCVerData_Data5_27 : 40|8@1+ (1,0) [0|255] "%"  PC
 SG_ S2P_CSCVerData_Data6_27 : 48|8@1+ (1,0) [0|255] "%"  PC
 SG_ S2P_CSCVerData_Data7_27 : 56|8@1+ (1,0) [0|255] "%"  PC

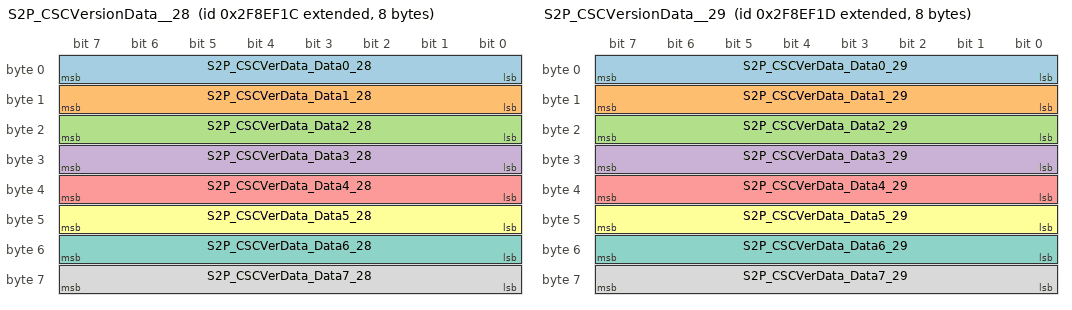
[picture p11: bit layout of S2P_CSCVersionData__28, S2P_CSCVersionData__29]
BO_ 2197352220 S2P_CSCVersionData__28: 8 SBMU
 SG_ S2P_CSCVerData_Data0_28 : 0|8@1+ (1,0) [0|255] "%"  PC
 SG_ S2P_CSCVerData_Data1_28 : 8|8@1+ (1,0) [0|255] "%"  PC
 SG_ S2P_CSCVerData_Data2_28 : 16|8@1+ (1,0) [0|255] "%"  PC
 SG_ S2P_CSCVerData_Data3_28 : 24|8@1+ (1,0) [0|255] "%"  PC
 SG_ S2P_CSCVerData_Data4_28 : 32|8@1+ (1,0) [0|255] "%"  PC
 SG_ S2P_CSCVerData_Data5_28 : 40|8@1+ (1,0) [0|255] "%"  PC
 SG_ S2P_CSCVerData_Data6_28 : 48|8@1+ (1,0) [0|255] "%"  PC
 SG_ S2P_CSCVerData_Data7_28 : 56|8@1+ (1,0) [0|255] "%"  PC

BO_ 2197352221 S2P_CSCVersionData__29: 8 SBMU
 SG_ S2P_CSCVerData_Data0_29 : 0|8@1+ (1,0) [0|255] "%"  PC
 SG_ S2P_CSCVerData_Data1_29 : 8|8@1+ (1,0) [0|255] "%"  PC
 SG_ S2P_CSCVerData_Data2_29 : 16|8@1+ (1,0) [0|255] "%"  PC
 SG_ S2P_CSCVerData_Data3_29 : 24|8@1+ (1,0) [0|255] "%"  PC
 SG_ S2P_CSCVerData_Data4_29 : 32|8@1+ (1,0) [0|255] "%"  PC
 SG_ S2P_CSCVerData_Data5_29 : 40|8@1+ (1,0) [0|255] "%"  PC
 SG_ S2P_CSCVerData_Data6_29 : 48|8@1+ (1,0) [0|255] "%"  PC
 SG_ S2P_CSCVerData_Data7_29 : 56|8@1+ (1,0) [0|255] "%"  PC

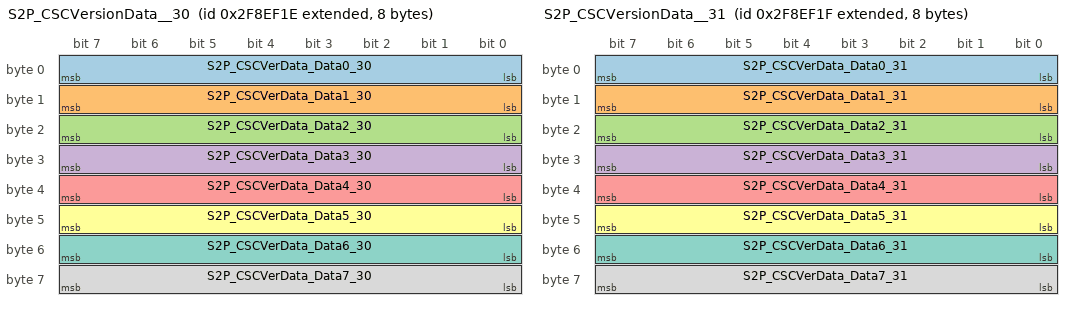
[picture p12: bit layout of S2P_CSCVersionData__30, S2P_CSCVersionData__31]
BO_ 2197352222 S2P_CSCVersionData__30: 8 SBMU
 SG_ S2P_CSCVerData_Data0_30 : 0|8@1+ (1,0) [0|255] "%"  PC
 SG_ S2P_CSCVerData_Data1_30 : 8|8@1+ (1,0) [0|255] "%"  PC
 SG_ S2P_CSCVerData_Data2_30 : 16|8@1+ (1,0) [0|255] "%"  PC
 SG_ S2P_CSCVerData_Data3_30 : 24|8@1+ (1,0) [0|255] "%"  PC
 SG_ S2P_CSCVerData_Data4_30 : 32|8@1+ (1,0) [0|255] "%"  PC
 SG_ S2P_CSCVerData_Data5_30 : 40|8@1+ (1,0) [0|255] "%"  PC
 SG_ S2P_CSCVerData_Data6_30 : 48|8@1+ (1,0) [0|255] "%"  PC
 SG_ S2P_CSCVerData_Data7_30 : 56|8@1+ (1,0) [0|255] "%"  PC

BO_ 2197352223 S2P_CSCVersionData__31: 8 SBMU
 SG_ S2P_CSCVerData_Data0_31 : 0|8@1+ (1,0) [0|255] "%"  PC
 SG_ S2P_CSCVerData_Data1_31 : 8|8@1+ (1,0) [0|255] "%"  PC
 SG_ S2P_CSCVerData_Data2_31 : 16|8@1+ (1,0) [0|255] "%"  PC
 SG_ S2P_CSCVerData_Data3_31 : 24|8@1+ (1,0) [0|255] "%"  PC
 SG_ S2P_CSCVerData_Data4_31 : 32|8@1+ (1,0) [0|255] "%"  PC
 SG_ S2P_CSCVerData_Data5_31 : 40|8@1+ (1,0) [0|255] "%"  PC
 SG_ S2P_CSCVerData_Data6_31 : 48|8@1+ (1,0) [0|255] "%"  PC
 SG_ S2P_CSCVerData_Data7_31 : 56|8@1+ (1,0) [0|255] "%"  PC

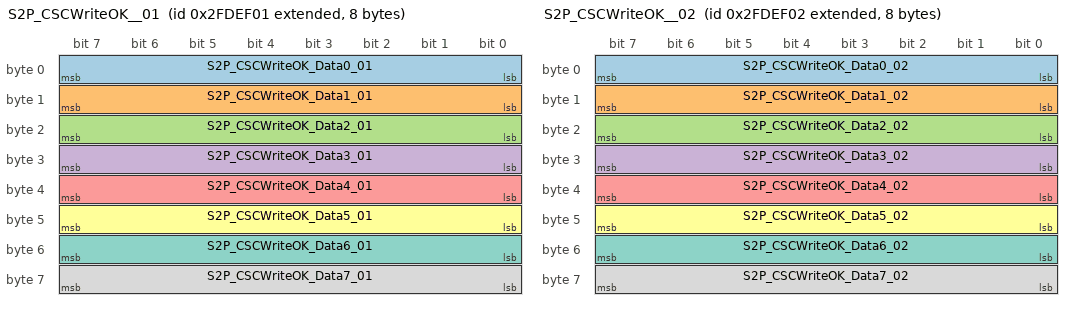
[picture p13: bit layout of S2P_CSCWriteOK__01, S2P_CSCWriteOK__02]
BO_ 2197679873 S2P_CSCWriteOK__01: 8 SBMU
 SG_ S2P_CSCWriteOK_Data0_01 : 0|8@1+ (1,0) [0|255] "%"  PC
 SG_ S2P_CSCWriteOK_Data1_01 : 8|8@1+ (1,0) [0|255] "%"  PC
 SG_ S2P_CSCWriteOK_Data2_01 : 16|8@1+ (1,0) [0|255] "%"  PC
 SG_ S2P_CSCWriteOK_Data3_01 : 24|8@1+ (1,0) [0|255] "%"  PC
 SG_ S2P_CSCWriteOK_Data4_01 : 32|8@1+ (1,0) [0|255] "%"  PC
 SG_ S2P_CSCWriteOK_Data5_01 : 40|8@1+ (1,0) [0|255] "%"  PC
 SG_ S2P_CSCWriteOK_Data6_01 : 48|8@1+ (1,0) [0|255] "%"  PC
 SG_ S2P_CSCWriteOK_Data7_01 : 56|8@1+ (1,0) [0|255] "%"  PC

BO_ 2197679874 S2P_CSCWriteOK__02: 8 SBMU
 SG_ S2P_CSCWriteOK_Data0_02 : 0|8@1+ (1,0) [0|255] "%"  PC
 SG_ S2P_CSCWriteOK_Data1_02 : 8|8@1+ (1,0) [0|255] "%"  PC
 SG_ S2P_CSCWriteOK_Data2_02 : 16|8@1+ (1,0) [0|255] "%"  PC
 SG_ S2P_CSCWriteOK_Data3_02 : 24|8@1+ (1,0) [0|255] "%"  PC
 SG_ S2P_CSCWriteOK_Data4_02 : 32|8@1+ (1,0) [0|255] "%"  PC
 SG_ S2P_CSCWriteOK_Data5_02 : 40|8@1+ (1,0) [0|255] "%"  PC
 SG_ S2P_CSCWriteOK_Data6_02 : 48|8@1+ (1,0) [0|255] "%"  PC
 SG_ S2P_CSCWriteOK_Data7_02 : 56|8@1+ (1,0) [0|255] "%"  PC

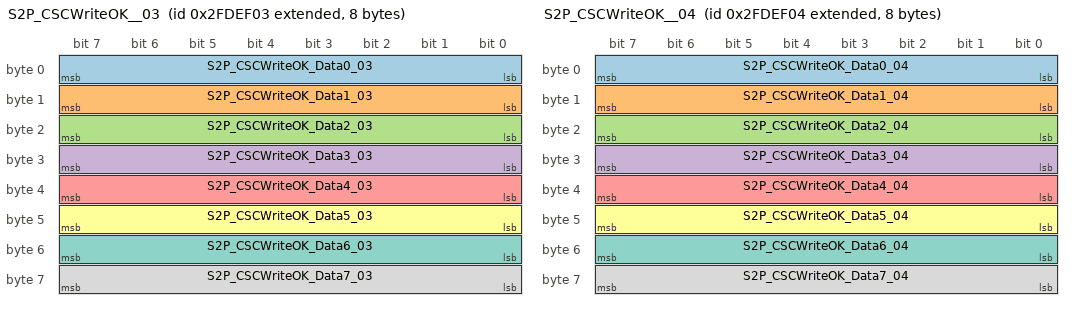
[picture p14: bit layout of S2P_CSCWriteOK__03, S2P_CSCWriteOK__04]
BO_ 2197679875 S2P_CSCWriteOK__03: 8 SBMU
 SG_ S2P_CSCWriteOK_Data0_03 : 0|8@1+ (1,0) [0|255] "%"  PC
 SG_ S2P_CSCWriteOK_Data1_03 : 8|8@1+ (1,0) [0|255] "%"  PC
 SG_ S2P_CSCWriteOK_Data2_03 : 16|8@1+ (1,0) [0|255] "%"  PC
 SG_ S2P_CSCWriteOK_Data3_03 : 24|8@1+ (1,0) [0|255] "%"  PC
 SG_ S2P_CSCWriteOK_Data4_03 : 32|8@1+ (1,0) [0|255] "%"  PC
 SG_ S2P_CSCWriteOK_Data5_03 : 40|8@1+ (1,0) [0|255] "%"  PC
 SG_ S2P_CSCWriteOK_Data6_03 : 48|8@1+ (1,0) [0|255] "%"  PC
 SG_ S2P_CSCWriteOK_Data7_03 : 56|8@1+ (1,0) [0|255] "%"  PC

BO_ 2197679876 S2P_CSCWriteOK__04: 8 SBMU
 SG_ S2P_CSCWriteOK_Data0_04 : 0|8@1+ (1,0) [0|255] "%"  PC
 SG_ S2P_CSCWriteOK_Data1_04 : 8|8@1+ (1,0) [0|255] "%"  PC
 SG_ S2P_CSCWriteOK_Data2_04 : 16|8@1+ (1,0) [0|255] "%"  PC
 SG_ S2P_CSCWriteOK_Data3_04 : 24|8@1+ (1,0) [0|255] "%"  PC
 SG_ S2P_CSCWriteOK_Data4_04 : 32|8@1+ (1,0) [0|255] "%"  PC
 SG_ S2P_CSCWriteOK_Data5_04 : 40|8@1+ (1,0) [0|255] "%"  PC
 SG_ S2P_CSCWriteOK_Data6_04 : 48|8@1+ (1,0) [0|255] "%"  PC
 SG_ S2P_CSCWriteOK_Data7_04 : 56|8@1+ (1,0) [0|255] "%"  PC

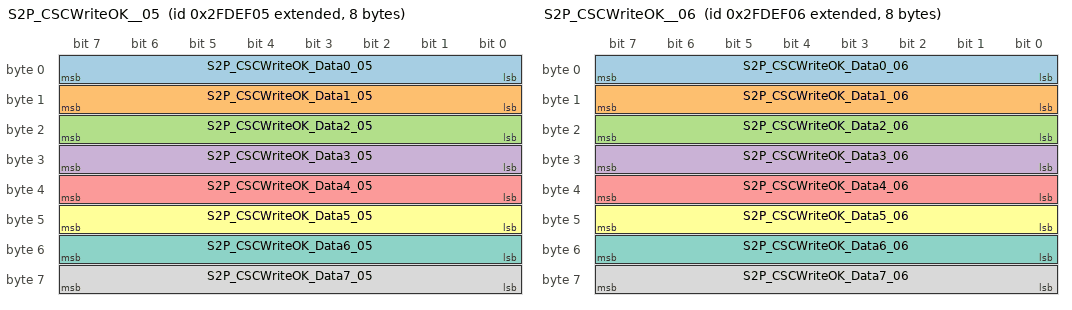
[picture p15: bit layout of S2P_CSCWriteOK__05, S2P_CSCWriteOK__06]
BO_ 2197679877 S2P_CSCWriteOK__05: 8 SBMU
 SG_ S2P_CSCWriteOK_Data0_05 : 0|8@1+ (1,0) [0|255] "%"  PC
 SG_ S2P_CSCWriteOK_Data1_05 : 8|8@1+ (1,0) [0|255] "%"  PC
 SG_ S2P_CSCWriteOK_Data2_05 : 16|8@1+ (1,0) [0|255] "%"  PC
 SG_ S2P_CSCWriteOK_Data3_05 : 24|8@1+ (1,0) [0|255] "%"  PC
 SG_ S2P_CSCWriteOK_Data4_05 : 32|8@1+ (1,0) [0|255] "%"  PC
 SG_ S2P_CSCWriteOK_Data5_05 : 40|8@1+ (1,0) [0|255] "%"  PC
 SG_ S2P_CSCWriteOK_Data6_05 : 48|8@1+ (1,0) [0|255] "%"  PC
 SG_ S2P_CSCWriteOK_Data7_05 : 56|8@1+ (1,0) [0|255] "%"  PC

BO_ 2197679878 S2P_CSCWriteOK__06: 8 SBMU
 SG_ S2P_CSCWriteOK_Data0_06 : 0|8@1+ (1,0) [0|255] "%"  PC
 SG_ S2P_CSCWriteOK_Data1_06 : 8|8@1+ (1,0) [0|255] "%"  PC
 SG_ S2P_CSCWriteOK_Data2_06 : 16|8@1+ (1,0) [0|255] "%"  PC
 SG_ S2P_CSCWriteOK_Data3_06 : 24|8@1+ (1,0) [0|255] "%"  PC
 SG_ S2P_CSCWriteOK_Data4_06 : 32|8@1+ (1,0) [0|255] "%"  PC
 SG_ S2P_CSCWriteOK_Data5_06 : 40|8@1+ (1,0) [0|255] "%"  PC
 SG_ S2P_CSCWriteOK_Data6_06 : 48|8@1+ (1,0) [0|255] "%"  PC
 SG_ S2P_CSCWriteOK_Data7_06 : 56|8@1+ (1,0) [0|255] "%"  PC

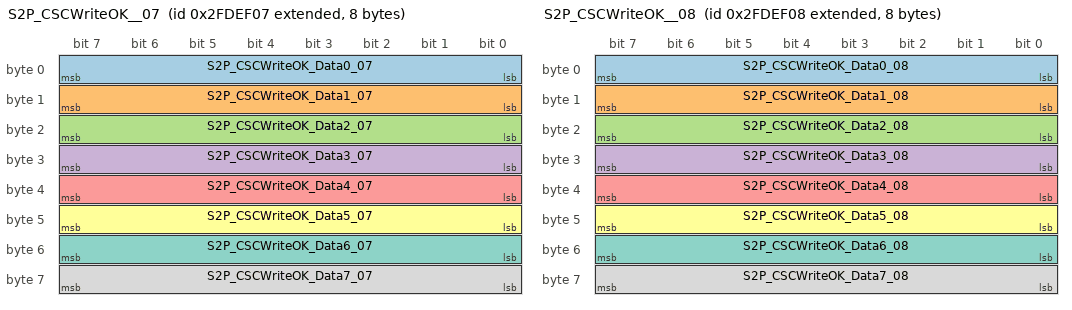
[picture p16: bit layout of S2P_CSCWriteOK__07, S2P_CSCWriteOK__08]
BO_ 2197679879 S2P_CSCWriteOK__07: 8 SBMU
 SG_ S2P_CSCWriteOK_Data0_07 : 0|8@1+ (1,0) [0|255] "%"  PC
 SG_ S2P_CSCWriteOK_Data1_07 : 8|8@1+ (1,0) [0|255] "%"  PC
 SG_ S2P_CSCWriteOK_Data2_07 : 16|8@1+ (1,0) [0|255] "%"  PC
 SG_ S2P_CSCWriteOK_Data3_07 : 24|8@1+ (1,0) [0|255] "%"  PC
 SG_ S2P_CSCWriteOK_Data4_07 : 32|8@1+ (1,0) [0|255] "%"  PC
 SG_ S2P_CSCWriteOK_Data5_07 : 40|8@1+ (1,0) [0|255] "%"  PC
 SG_ S2P_CSCWriteOK_Data6_07 : 48|8@1+ (1,0) [0|255] "%"  PC
 SG_ S2P_CSCWriteOK_Data7_07 : 56|8@1+ (1,0) [0|255] "%"  PC

BO_ 2197679880 S2P_CSCWriteOK__08: 8 SBMU
 SG_ S2P_CSCWriteOK_Data0_08 : 0|8@1+ (1,0) [0|255] "%"  PC
 SG_ S2P_CSCWriteOK_Data1_08 : 8|8@1+ (1,0) [0|255] "%"  PC
 SG_ S2P_CSCWriteOK_Data2_08 : 16|8@1+ (1,0) [0|255] "%"  PC
 SG_ S2P_CSCWriteOK_Data3_08 : 24|8@1+ (1,0) [0|255] "%"  PC
 SG_ S2P_CSCWriteOK_Data4_08 : 32|8@1+ (1,0) [0|255] "%"  PC
 SG_ S2P_CSCWriteOK_Data5_08 : 40|8@1+ (1,0) [0|255] "%"  PC
 SG_ S2P_CSCWriteOK_Data6_08 : 48|8@1+ (1,0) [0|255] "%"  PC
 SG_ S2P_CSCWriteOK_Data7_08 : 56|8@1+ (1,0) [0|255] "%"  PC

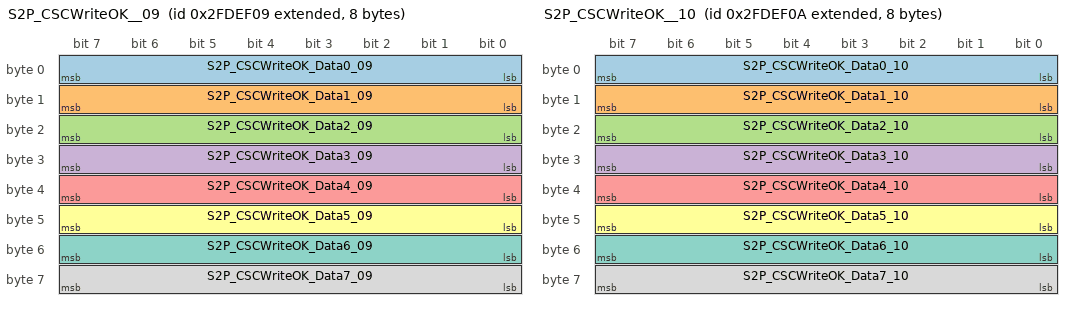
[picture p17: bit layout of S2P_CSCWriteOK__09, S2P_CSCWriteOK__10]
BO_ 2197679881 S2P_CSCWriteOK__09: 8 SBMU
 SG_ S2P_CSCWriteOK_Data0_09 : 0|8@1+ (1,0) [0|255] "%"  PC
 SG_ S2P_CSCWriteOK_Data1_09 : 8|8@1+ (1,0) [0|255] "%"  PC
 SG_ S2P_CSCWriteOK_Data2_09 : 16|8@1+ (1,0) [0|255] "%"  PC
 SG_ S2P_CSCWriteOK_Data3_09 : 24|8@1+ (1,0) [0|255] "%"  PC
 SG_ S2P_CSCWriteOK_Data4_09 : 32|8@1+ (1,0) [0|255] "%"  PC
 SG_ S2P_CSCWriteOK_Data5_09 : 40|8@1+ (1,0) [0|255] "%"  PC
 SG_ S2P_CSCWriteOK_Data6_09 : 48|8@1+ (1,0) [0|255] "%"  PC
 SG_ S2P_CSCWriteOK_Data7_09 : 56|8@1+ (1,0) [0|255] "%"  PC

BO_ 2197679882 S2P_CSCWriteOK__10: 8 SBMU
 SG_ S2P_CSCWriteOK_Data0_10 : 0|8@1+ (1,0) [0|255] "%"  PC
 SG_ S2P_CSCWriteOK_Data1_10 : 8|8@1+ (1,0) [0|255] "%"  PC
 SG_ S2P_CSCWriteOK_Data2_10 : 16|8@1+ (1,0) [0|255] "%"  PC
 SG_ S2P_CSCWriteOK_Data3_10 : 24|8@1+ (1,0) [0|255] "%"  PC
 SG_ S2P_CSCWriteOK_Data4_10 : 32|8@1+ (1,0) [0|255] "%"  PC
 SG_ S2P_CSCWriteOK_Data5_10 : 40|8@1+ (1,0) [0|255] "%"  PC
 SG_ S2P_CSCWriteOK_Data6_10 : 48|8@1+ (1,0) [0|255] "%"  PC
 SG_ S2P_CSCWriteOK_Data7_10 : 56|8@1+ (1,0) [0|255] "%"  PC

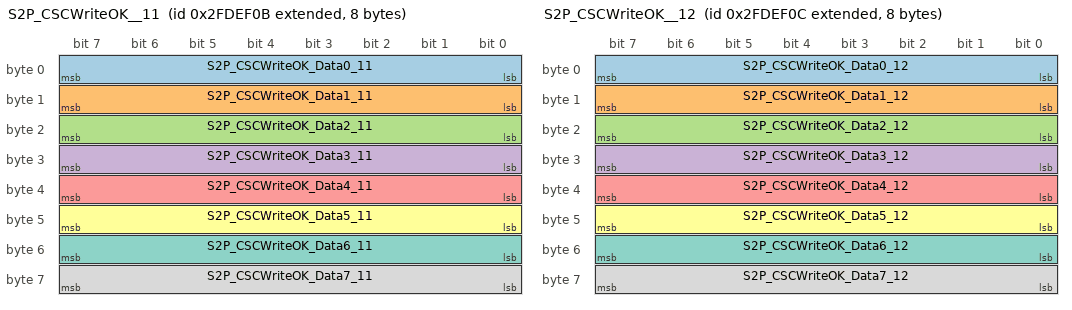
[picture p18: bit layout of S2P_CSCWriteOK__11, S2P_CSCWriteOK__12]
BO_ 2197679883 S2P_CSCWriteOK__11: 8 SBMU
 SG_ S2P_CSCWriteOK_Data0_11 : 0|8@1+ (1,0) [0|255] "%"  PC
 SG_ S2P_CSCWriteOK_Data1_11 : 8|8@1+ (1,0) [0|255] "%"  PC
 SG_ S2P_CSCWriteOK_Data2_11 : 16|8@1+ (1,0) [0|255] "%"  PC
 SG_ S2P_CSCWriteOK_Data3_11 : 24|8@1+ (1,0) [0|255] "%"  PC
 SG_ S2P_CSCWriteOK_Data4_11 : 32|8@1+ (1,0) [0|255] "%"  PC
 SG_ S2P_CSCWriteOK_Data5_11 : 40|8@1+ (1,0) [0|255] "%"  PC
 SG_ S2P_CSCWriteOK_Data6_11 : 48|8@1+ (1,0) [0|255] "%"  PC
 SG_ S2P_CSCWriteOK_Data7_11 : 56|8@1+ (1,0) [0|255] "%"  PC

BO_ 2197679884 S2P_CSCWriteOK__12: 8 SBMU
 SG_ S2P_CSCWriteOK_Data0_12 : 0|8@1+ (1,0) [0|255] "%"  PC
 SG_ S2P_CSCWriteOK_Data1_12 : 8|8@1+ (1,0) [0|255] "%"  PC
 SG_ S2P_CSCWriteOK_Data2_12 : 16|8@1+ (1,0) [0|255] "%"  PC
 SG_ S2P_CSCWriteOK_Data3_12 : 24|8@1+ (1,0) [0|255] "%"  PC
 SG_ S2P_CSCWriteOK_Data4_12 : 32|8@1+ (1,0) [0|255] "%"  PC
 SG_ S2P_CSCWriteOK_Data5_12 : 40|8@1+ (1,0) [0|255] "%"  PC
 SG_ S2P_CSCWriteOK_Data6_12 : 48|8@1+ (1,0) [0|255] "%"  PC
 SG_ S2P_CSCWriteOK_Data7_12 : 56|8@1+ (1,0) [0|255] "%"  PC

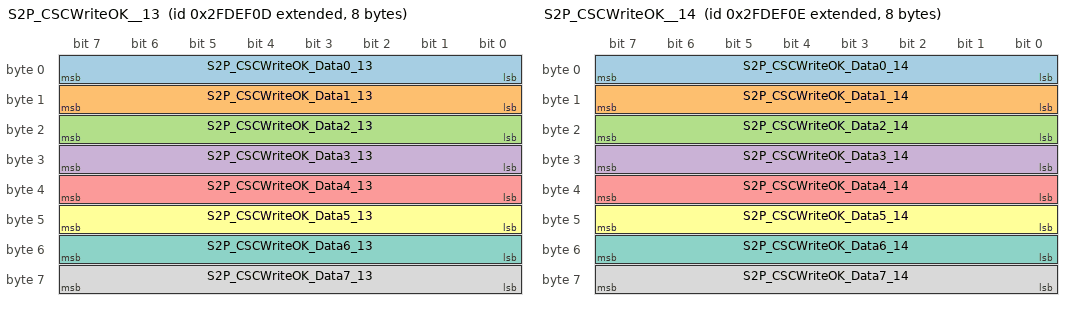
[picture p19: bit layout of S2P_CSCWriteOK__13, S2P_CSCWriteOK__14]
BO_ 2197679885 S2P_CSCWriteOK__13: 8 SBMU
 SG_ S2P_CSCWriteOK_Data0_13 : 0|8@1+ (1,0) [0|255] "%"  PC
 SG_ S2P_CSCWriteOK_Data1_13 : 8|8@1+ (1,0) [0|255] "%"  PC
 SG_ S2P_CSCWriteOK_Data2_13 : 16|8@1+ (1,0) [0|255] "%"  PC
 SG_ S2P_CSCWriteOK_Data3_13 : 24|8@1+ (1,0) [0|255] "%"  PC
 SG_ S2P_CSCWriteOK_Data4_13 : 32|8@1+ (1,0) [0|255] "%"  PC
 SG_ S2P_CSCWriteOK_Data5_13 : 40|8@1+ (1,0) [0|255] "%"  PC
 SG_ S2P_CSCWriteOK_Data6_13 : 48|8@1+ (1,0) [0|255] "%"  PC
 SG_ S2P_CSCWriteOK_Data7_13 : 56|8@1+ (1,0) [0|255] "%"  PC

BO_ 2197679886 S2P_CSCWriteOK__14: 8 SBMU
 SG_ S2P_CSCWriteOK_Data0_14 : 0|8@1+ (1,0) [0|255] "%"  PC
 SG_ S2P_CSCWriteOK_Data1_14 : 8|8@1+ (1,0) [0|255] "%"  PC
 SG_ S2P_CSCWriteOK_Data2_14 : 16|8@1+ (1,0) [0|255] "%"  PC
 SG_ S2P_CSCWriteOK_Data3_14 : 24|8@1+ (1,0) [0|255] "%"  PC
 SG_ S2P_CSCWriteOK_Data4_14 : 32|8@1+ (1,0) [0|255] "%"  PC
 SG_ S2P_CSCWriteOK_Data5_14 : 40|8@1+ (1,0) [0|255] "%"  PC
 SG_ S2P_CSCWriteOK_Data6_14 : 48|8@1+ (1,0) [0|255] "%"  PC
 SG_ S2P_CSCWriteOK_Data7_14 : 56|8@1+ (1,0) [0|255] "%"  PC

BO_ 2197679887 S2P_CSCWriteOK__15: 8 SBMU
 SG_ S2P_CSCWriteOK_Data0_15 : 0|8@1+ (1,0) [0|255] "%"  PC
 SG_ S2P_CSCWriteOK_Data1_15 : 8|8@1+ (1,0) [0|255] "%"  PC
 SG_ S2P_CSCWriteOK_Data2_15 : 16|8@1+ (1,0) [0|255] "%"  PC
 SG_ S2P_CSCWriteOK_Data3_15 : 24|8@1+ (1,0) [0|255] "%"  PC
 SG_ S2P_CSCWriteOK_Data4_15 : 32|8@1+ (1,0) [0|255] "%"  PC
 SG_ S2P_CSCWriteOK_Data5_15 : 40|8@1+ (1,0) [0|255] "%"  PC
 SG_ S2P_CSCWriteOK_Data6_15 : 48|8@1+ (1,0) [0|255] "%"  PC
 SG_ S2P_CSCWriteOK_Data7_15 : 56|8@1+ (1,0) [0|255] "%"  PC

BO_ 2197679888 S2P_CSCWriteOK__16: 8 SBMU
 SG_ S2P_CSCWriteOK_Data0_16 : 0|8@1+ (1,0) [0|255] "%"  PC
 SG_ S2P_CSCWriteOK_Data1_16 : 8|8@1+ (1,0) [0|255] "%"  PC
 SG_ S2P_CSCWriteOK_Data2_16 : 16|8@1+ (1,0) [0|255] "%"  PC
 SG_ S2P_CSCWriteOK_Data3_16 : 24|8@1+ (1,0) [0|255] "%"  PC
 SG_ S2P_CSCWriteOK_Data4_16 : 32|8@1+ (1,0) [0|255] "%"  PC
 SG_ S2P_CSCWriteOK_Data5_16 : 40|8@1+ (1,0) [0|255] "%"  PC
 SG_ S2P_CSCWriteOK_Data6_16 : 48|8@1+ (1,0) [0|255] "%"  PC
 SG_ S2P_CSCWriteOK_Data7_16 : 56|8@1+ (1,0) [0|255] "%"  PC

BO_ 2197679889 S2P_CSCWriteOK__17: 8 SBMU
 SG_ S2P_CSCWriteOK_Data0_17 : 0|8@1+ (1,0) [0|255] "%"  PC
 SG_ S2P_CSCWriteOK_Data1_17 : 8|8@1+ (1,0) [0|255] "%"  PC
 SG_ S2P_CSCWriteOK_Data2_17 : 16|8@1+ (1,0) [0|255] "%"  PC
 SG_ S2P_CSCWriteOK_Data3_17 : 24|8@1+ (1,0) [0|255] "%"  PC
 SG_ S2P_CSCWriteOK_Data4_17 : 32|8@1+ (1,0) [0|255] "%"  PC
 SG_ S2P_CSCWriteOK_Data5_17 : 40|8@1+ (1,0) [0|255] "%"  PC
 SG_ S2P_CSCWriteOK_Data6_17 : 48|8@1+ (1,0) [0|255] "%"  PC
 SG_ S2P_CSCWriteOK_Data7_17 : 56|8@1+ (1,0) [0|255] "%"  PC

BO_ 2197679890 S2P_CSCWriteOK__18: 8 SBMU
 SG_ S2P_CSCWriteOK_Data0_18 : 0|8@1+ (1,0) [0|255] "%"  PC
 SG_ S2P_CSCWriteOK_Data1_18 : 8|8@1+ (1,0) [0|255] "%"  PC
 SG_ S2P_CSCWriteOK_Data2_18 : 16|8@1+ (1,0) [0|255] "%"  PC
 SG_ S2P_CSCWriteOK_Data3_18 : 24|8@1+ (1,0) [0|255] "%"  PC
 SG_ S2P_CSCWriteOK_Data4_18 : 32|8@1+ (1,0) [0|255] "%"  PC
 SG_ S2P_CSCWriteOK_Data5_18 : 40|8@1+ (1,0) [0|255] "%"  PC
 SG_ S2P_CSCWriteOK_Data6_18 : 48|8@1+ (1,0) [0|255] "%"  PC
 SG_ S2P_CSCWriteOK_Data7_18 : 56|8@1+ (1,0) [0|255] "%"  PC

BO_ 2197679891 S2P_CSCWriteOK__19: 8 SBMU
 SG_ S2P_CSCWriteOK_Data0_19 : 0|8@1+ (1,0) [0|255] "%"  PC
 SG_ S2P_CSCWriteOK_Data1_19 : 8|8@1+ (1,0) [0|255] "%"  PC
 SG_ S2P_CSCWriteOK_Data2_19 : 16|8@1+ (1,0) [0|255] "%"  PC
 SG_ S2P_CSCWriteOK_Data3_19 : 24|8@1+ (1,0) [0|255] "%"  PC
 SG_ S2P_CSCWriteOK_Data4_19 : 32|8@1+ (1,0) [0|255] "%"  PC
 SG_ S2P_CSCWriteOK_Data5_19 : 40|8@1+ (1,0) [0|255] "%"  PC
 SG_ S2P_CSCWriteOK_Data6_19 : 48|8@1+ (1,0) [0|255] "%"  PC
 SG_ S2P_CSCWriteOK_Data7_19 : 56|8@1+ (1,0) [0|255] "%"  PC

BO_ 2197679892 S2P_CSCWriteOK__20: 8 SBMU
 SG_ S2P_CSCWriteOK_Data0_20 : 0|8@1+ (1,0) [0|255] "%"  PC
 SG_ S2P_CSCWriteOK_Data1_20 : 8|8@1+ (1,0) [0|255] "%"  PC
 SG_ S2P_CSCWriteOK_Data2_20 : 16|8@1+ (1,0) [0|255] "%"  PC
 SG_ S2P_CSCWriteOK_Data3_20 : 24|8@1+ (1,0) [0|255] "%"  PC
 SG_ S2P_CSCWriteOK_Data4_20 : 32|8@1+ (1,0) [0|255] "%"  PC
 SG_ S2P_CSCWriteOK_Data5_20 : 40|8@1+ (1,0) [0|255] "%"  PC
 SG_ S2P_CSCWriteOK_Data6_20 : 48|8@1+ (1,0) [0|255] "%"  PC
 SG_ S2P_CSCWriteOK_Data7_20 : 56|8@1+ (1,0) [0|255] "%"  PC

BO_ 2197679893 S2P_CSCWriteOK__21: 8 SBMU
 SG_ S2P_CSCWriteOK_Data0_21 : 0|8@1+ (1,0) [0|255] "%"  PC
 SG_ S2P_CSCWriteOK_Data1_21 : 8|8@1+ (1,0) [0|255] "%"  PC
 SG_ S2P_CSCWriteOK_Data2_21 : 16|8@1+ (1,0) [0|255] "%"  PC
 SG_ S2P_CSCWriteOK_Data3_21 : 24|8@1+ (1,0) [0|255] "%"  PC
 SG_ S2P_CSCWriteOK_Data4_21 : 32|8@1+ (1,0) [0|255] "%"  PC
 SG_ S2P_CSCWriteOK_Data5_21 : 40|8@1+ (1,0) [0|255] "%"  PC
 SG_ S2P_CSCWriteOK_Data6_21 : 48|8@1+ (1,0) [0|255] "%"  PC
 SG_ S2P_CSCWriteOK_Data7_21 : 56|8@1+ (1,0) [0|255] "%"  PC

BO_ 2197679894 S2P_CSCWriteOK__22: 8 SBMU
 SG_ S2P_CSCWriteOK_Data0_22 : 0|8@1+ (1,0) [0|255] "%"  PC
 SG_ S2P_CSCWriteOK_Data1_22 : 8|8@1+ (1,0) [0|255] "%"  PC
 SG_ S2P_CSCWriteOK_Data2_22 : 16|8@1+ (1,0) [0|255] "%"  PC
 SG_ S2P_CSCWriteOK_Data3_22 : 24|8@1+ (1,0) [0|255] "%"  PC
 SG_ S2P_CSCWriteOK_Data4_22 : 32|8@1+ (1,0) [0|255] "%"  PC
 SG_ S2P_CSCWriteOK_Data5_22 : 40|8@1+ (1,0) [0|255] "%"  PC
 SG_ S2P_CSCWriteOK_Data6_22 : 48|8@1+ (1,0) [0|255] "%"  PC
 SG_ S2P_CSCWriteOK_Data7_22 : 56|8@1+ (1,0) [0|255] "%"  PC

BO_ 2197679895 S2P_CSCWriteOK__23: 8 SBMU
 SG_ S2P_CSCWriteOK_Data0_23 : 0|8@1+ (1,0) [0|255] "%"  PC
 SG_ S2P_CSCWriteOK_Data1_23 : 8|8@1+ (1,0) [0|255] "%"  PC
 SG_ S2P_CSCWriteOK_Data2_23 : 16|8@1+ (1,0) [0|255] "%"  PC
 SG_ S2P_CSCWriteOK_Data3_23 : 24|8@1+ (1,0) [0|255] "%"  PC
 SG_ S2P_CSCWriteOK_Data4_23 : 32|8@1+ (1,0) [0|255] "%"  PC
 SG_ S2P_CSCWriteOK_Data5_23 : 40|8@1+ (1,0) [0|255] "%"  PC
 SG_ S2P_CSCWriteOK_Data6_23 : 48|8@1+ (1,0) [0|255] "%"  PC
 SG_ S2P_CSCWriteOK_Data7_23 : 56|8@1+ (1,0) [0|255] "%"  PC

BO_ 2197679896 S2P_CSCWriteOK__24: 8 SBMU
 SG_ S2P_CSCWriteOK_Data0_24 : 0|8@1+ (1,0) [0|255] "%"  PC
 SG_ S2P_CSCWriteOK_Data1_24 : 8|8@1+ (1,0) [0|255] "%"  PC
 SG_ S2P_CSCWriteOK_Data2_24 : 16|8@1+ (1,0) [0|255] "%"  PC
 SG_ S2P_CSCWriteOK_Data3_24 : 24|8@1+ (1,0) [0|255] "%"  PC
 SG_ S2P_CSCWriteOK_Data4_24 : 32|8@1+ (1,0) [0|255] "%"  PC
 SG_ S2P_CSCWriteOK_Data5_24 : 40|8@1+ (1,0) [0|255] "%"  PC
 SG_ S2P_CSCWriteOK_Data6_24 : 48|8@1+ (1,0) [0|255] "%"  PC
 SG_ S2P_CSCWriteOK_Data7_24 : 56|8@1+ (1,0) [0|255] "%"  PC

BO_ 2197679897 S2P_CSCWriteOK__25: 8 SBMU
 SG_ S2P_CSCWriteOK_Data0_25 : 0|8@1+ (1,0) [0|255] "%"  PC
 SG_ S2P_CSCWriteOK_Data1_25 : 8|8@1+ (1,0) [0|255] "%"  PC
 SG_ S2P_CSCWriteOK_Data2_25 : 16|8@1+ (1,0) [0|255] "%"  PC
 SG_ S2P_CSCWriteOK_Data3_25 : 24|8@1+ (1,0) [0|255] "%"  PC
 SG_ S2P_CSCWriteOK_Data4_25 : 32|8@1+ (1,0) [0|255] "%"  PC
 SG_ S2P_CSCWriteOK_Data5_25 : 40|8@1+ (1,0) [0|255] "%"  PC
 SG_ S2P_CSCWriteOK_Data6_25 : 48|8@1+ (1,0) [0|255] "%"  PC
 SG_ S2P_CSCWriteOK_Data7_25 : 56|8@1+ (1,0) [0|255] "%"  PC

BO_ 2197679898 S2P_CSCWriteOK__26: 8 SBMU
 SG_ S2P_CSCWriteOK_Data0_26 : 0|8@1+ (1,0) [0|255] "%"  PC
 SG_ S2P_CSCWriteOK_Data1_26 : 8|8@1+ (1,0) [0|255] "%"  PC
 SG_ S2P_CSCWriteOK_Data2_26 : 16|8@1+ (1,0) [0|255] "%"  PC
 SG_ S2P_CSCWriteOK_Data3_26 : 24|8@1+ (1,0) [0|255] "%"  PC
 SG_ S2P_CSCWriteOK_Data4_26 : 32|8@1+ (1,0) [0|255] "%"  PC
 SG_ S2P_CSCWriteOK_Data5_26 : 40|8@1+ (1,0) [0|255] "%"  PC
 SG_ S2P_CSCWriteOK_Data6_26 : 48|8@1+ (1,0) [0|255] "%"  PC
 SG_ S2P_CSCWriteOK_Data7_26 : 56|8@1+ (1,0) [0|255] "%"  PC

BO_ 2197679899 S2P_CSCWriteOK__27: 8 SBMU
 SG_ S2P_CSCWriteOK_Data0_27 : 0|8@1+ (1,0) [0|255] "%"  PC
 SG_ S2P_CSCWriteOK_Data1_27 : 8|8@1+ (1,0) [0|255] "%"  PC
 SG_ S2P_CSCWriteOK_Data2_27 : 16|8@1+ (1,0) [0|255] "%"  PC
 SG_ S2P_CSCWriteOK_Data3_27 : 24|8@1+ (1,0) [0|255] "%"  PC
 SG_ S2P_CSCWriteOK_Data4_27 : 32|8@1+ (1,0) [0|255] "%"  PC
 SG_ S2P_CSCWriteOK_Data5_27 : 40|8@1+ (1,0) [0|255] "%"  PC
 SG_ S2P_CSCWriteOK_Data6_27 : 48|8@1+ (1,0) [0|255] "%"  PC
 SG_ S2P_CSCWriteOK_Data7_27 : 56|8@1+ (1,0) [0|255] "%"  PC

BO_ 2197679900 S2P_CSCWriteOK__28: 8 SBMU
 SG_ S2P_CSCWriteOK_Data0_28 : 0|8@1+ (1,0) [0|255] "%"  PC
 SG_ S2P_CSCWriteOK_Data1_28 : 8|8@1+ (1,0) [0|255] "%"  PC
 SG_ S2P_CSCWriteOK_Data2_28 : 16|8@1+ (1,0) [0|255] "%"  PC
 SG_ S2P_CSCWriteOK_Data3_28 : 24|8@1+ (1,0) [0|255] "%"  PC
 SG_ S2P_CSCWriteOK_Data4_28 : 32|8@1+ (1,0) [0|255] "%"  PC
 SG_ S2P_CSCWriteOK_Data5_28 : 40|8@1+ (1,0) [0|255] "%"  PC
 SG_ S2P_CSCWriteOK_Data6_28 : 48|8@1+ (1,0) [0|255] "%"  PC
 SG_ S2P_CSCWriteOK_Data7_28 : 56|8@1+ (1,0) [0|255] "%"  PC

BO_ 2197679901 S2P_CSCWriteOK__29: 8 SBMU
 SG_ S2P_CSCWriteOK_Data0_29 : 0|8@1+ (1,0) [0|255] "%"  PC
 SG_ S2P_CSCWriteOK_Data1_29 : 8|8@1+ (1,0) [0|255] "%"  PC
 SG_ S2P_CSCWriteOK_Data2_29 : 16|8@1+ (1,0) [0|255] "%"  PC
 SG_ S2P_CSCWriteOK_Data3_29 : 24|8@1+ (1,0) [0|255] "%"  PC
 SG_ S2P_CSCWriteOK_Data4_29 : 32|8@1+ (1,0) [0|255] "%"  PC
 SG_ S2P_CSCWriteOK_Data5_29 : 40|8@1+ (1,0) [0|255] "%"  PC
 SG_ S2P_CSCWriteOK_Data6_29 : 48|8@1+ (1,0) [0|255] "%"  PC
 SG_ S2P_CSCWriteOK_Data7_29 : 56|8@1+ (1,0) [0|255] "%"  PC

BO_ 2197679902 S2P_CSCWriteOK__30: 8 SBMU
 SG_ S2P_CSCWriteOK_Data0_30 : 0|8@1+ (1,0) [0|255] "%"  PC
 SG_ S2P_CSCWriteOK_Data1_30 : 8|8@1+ (1,0) [0|255] "%"  PC
 SG_ S2P_CSCWriteOK_Data2_30 : 16|8@1+ (1,0) [0|255] "%"  PC
 SG_ S2P_CSCWriteOK_Data3_30 : 24|8@1+ (1,0) [0|255] "%"  PC
 SG_ S2P_CSCWriteOK_Data4_30 : 32|8@1+ (1,0) [0|255] "%"  PC
 SG_ S2P_CSCWriteOK_Data5_30 : 40|8@1+ (1,0) [0|255] "%"  PC
 SG_ S2P_CSCWriteOK_Data6_30 : 48|8@1+ (1,0) [0|255] "%"  PC
 SG_ S2P_CSCWriteOK_Data7_30 : 56|8@1+ (1,0) [0|255] "%"  PC

BO_ 2197679903 S2P_CSCWriteOK__31: 8 SBMU
 SG_ S2P_CSCWriteOK_Data0_31 : 0|8@1+ (1,0) [0|255] "%"  PC
 SG_ S2P_CSCWriteOK_Data1_31 : 8|8@1+ (1,0) [0|255] "%"  PC
 SG_ S2P_CSCWriteOK_Data2_31 : 16|8@1+ (1,0) [0|255] "%"  PC
 SG_ S2P_CSCWriteOK_Data3_31 : 24|8@1+ (1,0) [0|255] "%"  PC
 SG_ S2P_CSCWriteOK_Data4_31 : 32|8@1+ (1,0) [0|255] "%"  PC
 SG_ S2P_CSCWriteOK_Data5_31 : 40|8@1+ (1,0) [0|255] "%"  PC
 SG_ S2P_CSCWriteOK_Data6_31 : 48|8@1+ (1,0) [0|255] "%"  PC
 SG_ S2P_CSCWriteOK_Data7_31 : 56|8@1+ (1,0) [0|255] "%"  PC

BO_ 2417815105 S2P_CSCPrgRslt__01: 8 SBMU
 SG_ S2P_CSCPrgRslt_CSCPosition_01 : 0|32@1+ (1,0) [0|4294967295] "%"  PC

BO_ 2417815106 S2P_CSCPrgRslt__02: 8 SBMU
 SG_ S2P_CSCPrgRslt_CSCPosition_02 : 0|32@1+ (1,0) [0|4294967295] "%"  PC

BO_ 2417815107 S2P_CSCPrgRslt__03: 8 SBMU
 SG_ S2P_CSCPrgRslt_CSCPosition_03 : 0|32@1+ (1,0) [0|4294967295] "%"  PC

BO_ 2417815108 S2P_CSCPrgRslt__04: 8 SBMU
 SG_ S2P_CSCPrgRslt_CSCPosition_04 : 0|32@1+ (1,0) [0|4294967295] "%"  PC

BO_ 2417815109 S2P_CSCPrgRslt__05: 8 SBMU
 SG_ S2P_CSCPrgRslt_CSCPosition_05 : 0|32@1+ (1,0) [0|4294967295] "%"  PC

BO_ 2417815110 S2P_CSCPrgRslt__06: 8 SBMU
 SG_ S2P_CSCPrgRslt_CSCPosition_06 : 0|32@1+ (1,0) [0|4294967295] "%"  PC

BO_ 2417815111 S2P_CSCPrgRslt__07: 8 SBMU
 SG_ S2P_CSCPrgRslt_CSCPosition_07 : 0|32@1+ (1,0) [0|4294967295] "%"  PC

BO_ 2417815112 S2P_CSCPrgRslt__08: 8 SBMU
 SG_ S2P_CSCPrgRslt_CSCPosition_08 : 0|32@1+ (1,0) [0|4294967295] "%"  PC

BO_ 2417815113 S2P_CSCPrgRslt__09: 8 SBMU
 SG_ S2P_CSCPrgRslt_CSCPosition_09 : 0|32@1+ (1,0) [0|4294967295] "%"  PC

BO_ 2417815114 S2P_CSCPrgRslt__10: 8 SBMU
 SG_ S2P_CSCPrgRslt_CSCPosition_10 : 0|32@1+ (1,0) [0|4294967295] "%"  PC

BO_ 2417815115 S2P_CSCPrgRslt__11: 8 SBMU
 SG_ S2P_CSCPrgRslt_CSCPosition_11 : 0|32@1+ (1,0) [0|4294967295] "%"  PC

BO_ 2417815116 S2P_CSCPrgRslt__12: 8 SBMU
 SG_ S2P_CSCPrgRslt_CSCPosition_12 : 0|32@1+ (1,0) [0|4294967295] "%"  PC

BO_ 2417815117 S2P_CSCPrgRslt__13: 8 SBMU
 SG_ S2P_CSCPrgRslt_CSCPosition_13 : 0|32@1+ (1,0) [0|4294967295] "%"  PC

BO_ 2417815118 S2P_CSCPrgRslt__14: 8 SBMU
 SG_ S2P_CSCPrgRslt_CSCPosition_14 : 0|32@1+ (1,0) [0|4294967295] "%"  PC

BO_ 2417815119 S2P_CSCPrgRslt__15: 8 SBMU
 SG_ S2P_CSCPrgRslt_CSCPosition_15 : 0|32@1+ (1,0) [0|4294967295] "%"  PC

BO_ 2417815120 S2P_CSCPrgRslt__16: 8 SBMU
 SG_ S2P_CSCPrgRslt_CSCPosition_16 : 0|32@1+ (1,0) [0|4294967295] "%"  PC

BO_ 2417815121 S2P_CSCPrgRslt__17: 8 SBMU
 SG_ S2P_CSCPrgRslt_CSCPosition_17 : 0|32@1+ (1,0) [0|4294967295] "%"  PC

BO_ 2417815122 S2P_CSCPrgRslt__18: 8 SBMU
 SG_ S2P_CSCPrgRslt_CSCPosition_18 : 0|32@1+ (1,0) [0|4294967295] "%"  PC

BO_ 2417815123 S2P_CSCPrgRslt__19: 8 SBMU
 SG_ S2P_CSCPrgRslt_CSCPosition_19 : 0|32@1+ (1,0) [0|4294967295] "%"  PC

BO_ 2417815124 S2P_CSCPrgRslt__20: 8 SBMU
 SG_ S2P_CSCPrgRslt_CSCPosition_20 : 0|32@1+ (1,0) [0|4294967295] "%"  PC

BO_ 2417815125 S2P_CSCPrgRslt__21: 8 SBMU
 SG_ S2P_CSCPrgRslt_CSCPosition_21 : 0|32@1+ (1,0) [0|4294967295] "%"  PC

BO_ 2417815126 S2P_CSCPrgRslt__22: 8 SBMU
 SG_ S2P_CSCPrgRslt_CSCPosition_22 : 0|32@1+ (1,0) [0|4294967295] "%"  PC

BO_ 2417815127 S2P_CSCPrgRslt__23: 8 SBMU
 SG_ S2P_CSCPrgRslt_CSCPosition_23 : 0|32@1+ (1,0) [0|4294967295] "%"  PC

BO_ 2417815128 S2P_CSCPrgRslt__24: 8 SBMU
 SG_ S2P_CSCPrgRslt_CSCPosition_24 : 0|32@1+ (1,0) [0|4294967295] "%"  PC

BO_ 2417815129 S2P_CSCPrgRslt__25: 8 SBMU
 SG_ S2P_CSCPrgRslt_CSCPosition_25 : 0|32@1+ (1,0) [0|4294967295] "%"  PC

BO_ 2417815130 S2P_CSCPrgRslt__26: 8 SBMU
 SG_ S2P_CSCPrgRslt_CSCPosition_26 : 0|32@1+ (1,0) [0|4294967295] "%"  PC

BO_ 2417815131 S2P_CSCPrgRslt__27: 8 SBMU
 SG_ S2P_CSCPrgRslt_CSCPosition_27 : 0|32@1+ (1,0) [0|4294967295] "%"  PC

BO_ 2417815132 S2P_CSCPrgRslt__28: 8 SBMU
 SG_ S2P_CSCPrgRslt_CSCPosition_28 : 0|32@1+ (1,0) [0|4294967295] "%"  PC

BO_ 2417815133 S2P_CSCPrgRslt__29: 8 SBMU
 SG_ S2P_CSCPrgRslt_CSCPosition_29 : 0|32@1+ (1,0) [0|4294967295] "%"  PC

BO_ 2417815134 S2P_CSCPrgRslt__30: 8 SBMU
 SG_ S2P_CSCPrgRslt_CSCPosition_30 : 0|32@1+ (1,0) [0|4294967295] "%"  PC

BO_ 2417815135 S2P_CSCPrgRslt__31: 8 SBMU
 SG_ S2P_CSCPrgRslt_CSCPosition_31 : 0|32@1+ (1,0) [0|4294967295] "%"  PC

BO_ 2417815136 S2P_CSCPrgRslt__32: 8 SBMU
 SG_ S2P_CSCPrgRslt_CSCPosition_32 : 0|32@1+ (1,0) [0|4294967295] "%"  PC

BO_ 2417815137 S2P_CSCPrgRslt__33: 8 SBMU
 SG_ S2P_CSCPrgRslt_CSCPosition_33 : 0|32@1+ (1,0) [0|4294967295] "%"  PC

BO_ 2417815138 S2P_CSCPrgRslt__34: 8 SBMU
 SG_ S2P_CSCPrgRslt_CSCPosition_34 : 0|32@1+ (1,0) [0|4294967295] "%"  PC

BO_ 2417815139 S2P_CSCPrgRslt__35: 8 SBMU
 SG_ S2P_CSCPrgRslt_CSCPosition_35 : 0|32@1+ (1,0) [0|4294967295] "%"  PC

BO_ 2417815140 S2P_CSCPrgRslt__36: 8 SBMU
 SG_ S2P_CSCPrgRslt_CSCPosition_36 : 0|32@1+ (1,0) [0|4294967295] "%"  PC

BO_ 2417815141 S2P_CSCPrgRslt__37: 8 SBMU
 SG_ S2P_CSCPrgRslt_CSCPosition_37 : 0|32@1+ (1,0) [0|4294967295] "%"  PC

BO_ 2417815142 S2P_CSCPrgRslt__38: 8 SBMU
 SG_ S2P_CSCPrgRslt_CSCPosition_38 : 0|32@1+ (1,0) [0|4294967295] "%"  PC

BO_ 2417815143 S2P_CSCPrgRslt__39: 8 SBMU
 SG_ S2P_CSCPrgRslt_CSCPosition_39 : 0|32@1+ (1,0) [0|4294967295] "%"  PC

BO_ 2417815144 S2P_CSCPrgRslt__40: 8 SBMU
 SG_ S2P_CSCPrgRslt_CSCPosition_40 : 0|32@1+ (1,0) [0|4294967295] "%"  PC

BO_ 2417815145 S2P_CSCPrgRslt__41: 8 SBMU
 SG_ S2P_CSCPrgRslt_CSCPosition_41 : 0|32@1+ (1,0) [0|4294967295] "%"  PC

BO_ 2417815146 S2P_CSCPrgRslt__42: 8 SBMU
 SG_ S2P_CSCPrgRslt_CSCPosition_42 : 0|32@1+ (1,0) [0|4294967295] "%"  PC

BO_ 2417815147 S2P_CSCPrgRslt__43: 8 SBMU
 SG_ S2P_CSCPrgRslt_CSCPosition_43 : 0|32@1+ (1,0) [0|4294967295] "%"  PC

BO_ 2417815148 S2P_CSCPrgRslt__44: 8 SBMU
 SG_ S2P_CSCPrgRslt_CSCPosition_44 : 0|32@1+ (1,0) [0|4294967295] "%"  PC

BO_ 2417815149 S2P_CSCPrgRslt__45: 8 SBMU
 SG_ S2P_CSCPrgRslt_CSCPosition_45 : 0|32@1+ (1,0) [0|4294967295] "%"  PC

BO_ 2417815150 S2P_CSCPrgRslt__46: 8 SBMU
 SG_ S2P_CSCPrgRslt_CSCPosition_46 : 0|32@1+ (1,0) [0|4294967295] "%"  PC

BO_ 2417815151 S2P_CSCPrgRslt__47: 8 SBMU
 SG_ S2P_CSCPrgRslt_CSCPosition_47 : 0|32@1+ (1,0) [0|4294967295] "%"  PC

BO_ 2417815152 S2P_CSCPrgRslt__48: 8 SBMU
 SG_ S2P_CSCPrgRslt_CSCPosition_48 : 0|32@1+ (1,0) [0|4294967295] "%"  PC

BO_ 2417815153 S2P_CSCPrgRslt__49: 8 SBMU
 SG_ S2P_CSCPrgRslt_CSCPosition_49 : 0|32@1+ (1,0) [0|4294967295] "%"  PC

BO_ 2417815154 S2P_CSCPrgRslt__50: 8 SBMU
 SG_ S2P_CSCPrgRslt_CSCPosition_50 : 0|32@1+ (1,0) [0|4294967295] "%"  PC

BO_ 2417815155 S2P_CSCPrgRslt__51: 8 SBMU
 SG_ S2P_CSCPrgRslt_CSCPosition_51 : 0|32@1+ (1,0) [0|4294967295] "%"  PC

BO_ 2417815156 S2P_CSCPrgRslt__52: 8 SBMU
 SG_ S2P_CSCPrgRslt_CSCPosition_52 : 0|32@1+ (1,0) [0|4294967295] "%"  PC

BO_ 2417815157 S2P_CSCPrgRslt__53: 8 SBMU
 SG_ S2P_CSCPrgRslt_CSCPosition_53 : 0|32@1+ (1,0) [0|4294967295] "%"  PC

BO_ 2417815158 S2P_CSCPrgRslt__54: 8 SBMU
 SG_ S2P_CSCPrgRslt_CSCPosition_54 : 0|32@1+ (1,0) [0|4294967295] "%"  PC

BO_ 2417815159 S2P_CSCPrgRslt__55: 8 SBMU
 SG_ S2P_CSCPrgRslt_CSCPosition_55 : 0|32@1+ (1,0) [0|4294967295] "%"  PC

BO_ 2417815160 S2P_CSCPrgRslt__56: 8 SBMU
 SG_ S2P_CSCPrgRslt_CSCPosition_56 : 0|32@1+ (1,0) [0|4294967295] "%"  PC

BO_ 2417815161 S2P_CSCPrgRslt__57: 8 SBMU
 SG_ S2P_CSCPrgRslt_CSCPosition_57 : 0|32@1+ (1,0) [0|4294967295] "%"  PC

BO_ 2417815162 S2P_CSCPrgRslt__58: 8 SBMU
 SG_ S2P_CSCPrgRslt_CSCPosition_58 : 0|32@1+ (1,0) [0|4294967295] "%"  PC

BO_ 2417815163 S2P_CSCPrgRslt__59: 8 SBMU
 SG_ S2P_CSCPrgRslt_CSCPosition_59 : 0|32@1+ (1,0) [0|4294967295] "%"  PC

BO_ 2417815164 S2P_CSCPrgRslt__60: 8 SBMU
 SG_ S2P_CSCPrgRslt_CSCPosition_60 : 0|32@1+ (1,0) [0|4294967295] "%"  PC

BO_ 2417815165 S2P_CSCPrgRslt__61: 8 SBMU
 SG_ S2P_CSCPrgRslt_CSCPosition_61 : 0|32@1+ (1,0) [0|4294967295] "%"  PC

BO_ 2417815166 S2P_CSCPrgRslt__62: 8 SBMU
 SG_ S2P_CSCPrgRslt_CSCPosition_62 : 0|32@1+ (1,0) [0|4294967295] "%"  PC

BO_ 2417815167 S2P_CSCPrgRslt__63: 8 SBMU
 SG_ S2P_CSCPrgRslt_CSCPosition_63 : 0|32@1+ (1,0) [0|4294967295] "%"  PC

BO_ 2148630417 M2S_CMD1__01: 8 MBMU
 SG_ HvPwrOnCmd_SBMU01_01 : 0|2@1+ (1,0) [0|3] ""  SBMU
 SG_ HvPwrOnCmd_SBMU02_01 : 2|2@1+ (1,0) [0|3] ""  SBMU
 SG_ HvPwrOnCmd_SBMU03_01 : 4|2@1+ (1,0) [0|3] ""  SBMU
 SG_ HvPwrOnCmd_SBMU04_01 : 6|2@1+ (1,0) [0|3] ""  SBMU
 SG_ HvPwrOnCmd_SBMU05_01 : 8|2@1+ (1,0) [0|3] ""  SBMU
 SG_ HvPwrOnCmd_SBMU06_01 : 10|2@1+ (1,0) [0|3] ""  SBMU
 SG_ HvPwrOnCmd_SBMU07_01 : 12|2@1+ (1,0) [0|3] ""  SBMU
 SG_ HvPwrOnCmd_SBMU08_01 : 14|2@1+ (1,0) [0|3] ""  SBMU
 SG_ HvPwrOnCmd_SBMU09_01 : 16|2@1+ (1,0) [0|3] ""  SBMU
 SG_ HvPwrOnCmd_SBMU10_01 : 18|2@1+ (1,0) [0|3] ""  SBMU
 SG_ HvPwrOnCmd_SBMU11_01 : 20|2@1+ (1,0) [0|3] ""  SBMU
 SG_ HvPwrOnCmd_SBMU12_01 : 22|2@1+ (1,0) [0|3] ""  SBMU
 SG_ HvPwrOnCmd_SBMU13_01 : 24|2@1+ (1,0) [0|3] ""  SBMU
 SG_ HvPwrOnCmd_SBMU14_01 : 26|2@1+ (1,0) [0|3] ""  SBMU
 SG_ HvPwrOnCmd_SBMU15_01 : 28|2@1+ (1,0) [0|3] ""  SBMU
 SG_ HvPwrOnCmd_SBMU16_01 : 30|2@1+ (1,0) [0|3] ""  SBMU
 SG_ HvPwrOnCmd_SBMU17_01 : 32|2@1+ (1,0) [0|3] ""  SBMU
 SG_ HvPwrOnCmd_SBMU18_01 : 34|2@1+ (1,0) [0|3] ""  SBMU
 SG_ HvPwrOnCmd_SBMU19_01 : 36|2@1+ (1,0) [0|3] ""  SBMU
 SG_ HvPwrOnCmd_SBMU20_01 : 38|2@1+ (1,0) [0|3] ""  SBMU
 SG_ HvPwrOnCmd_SBMU21_01 : 40|2@1+ (1,0) [0|3] ""  SBMU
 SG_ HvPwrOnCmd_SBMU22_01 : 42|2@1+ (1,0) [0|3] ""  SBMU
 SG_ HvPwrOnCmd_SBMU23_01 : 44|2@1+ (1,0) [0|3] ""  SBMU
 SG_ HvPwrOnCmd_SBMU24_01 : 46|2@1+ (1,0) [0|3] ""  SBMU
 SG_ HvPwrOnCmd_SBMU25_01 : 48|2@1+ (1,0) [0|3] ""  SBMU
 SG_ HvPwrOnCmd_SBMU26_01 : 50|2@1+ (1,0) [0|3] ""  SBMU
 SG_ HvPwrOnCmd_SBMU27_01 : 52|2@1+ (1,0) [0|3] ""  SBMU
 SG_ HvPwrOnCmd_SBMU28_01 : 54|2@1+ (1,0) [0|3] ""  SBMU
 SG_ HvPwrOnCmd_SBMU29_01 : 56|2@1+ (1,0) [0|3] ""  SBMU
 SG_ HvPwrOnCmd_SBMU30_01 : 58|2@1+ (1,0) [0|3] ""  SBMU
 SG_ HvPwrOnCmd_SBMU31_01 : 60|2@1+ (1,0) [0|3] ""  SBMU
 SG_ HvPwrOnCmd_SBMU32_01 : 62|2@1+ (1,0) [0|3] ""  SBMU

BO_ 2148630418 M2S_CMD1__02: 8 MBMU
 SG_ HvPwrOnCmd_SBMU01_02 : 0|2@1+ (1,0) [0|3] ""  SBMU
 SG_ HvPwrOnCmd_SBMU02_02 : 2|2@1+ (1,0) [0|3] ""  SBMU
 SG_ HvPwrOnCmd_SBMU03_02 : 4|2@1+ (1,0) [0|3] ""  SBMU
 SG_ HvPwrOnCmd_SBMU04_02 : 6|2@1+ (1,0) [0|3] ""  SBMU
 SG_ HvPwrOnCmd_SBMU05_02 : 8|2@1+ (1,0) [0|3] ""  SBMU
 SG_ HvPwrOnCmd_SBMU06_02 : 10|2@1+ (1,0) [0|3] ""  SBMU
 SG_ HvPwrOnCmd_SBMU07_02 : 12|2@1+ (1,0) [0|3] ""  SBMU
 SG_ HvPwrOnCmd_SBMU08_02 : 14|2@1+ (1,0) [0|3] ""  SBMU
 SG_ HvPwrOnCmd_SBMU09_02 : 16|2@1+ (1,0) [0|3] ""  SBMU
 SG_ HvPwrOnCmd_SBMU10_02 : 18|2@1+ (1,0) [0|3] ""  SBMU
 SG_ HvPwrOnCmd_SBMU11_02 : 20|2@1+ (1,0) [0|3] ""  SBMU
 SG_ HvPwrOnCmd_SBMU12_02 : 22|2@1+ (1,0) [0|3] ""  SBMU
 SG_ HvPwrOnCmd_SBMU13_02 : 24|2@1+ (1,0) [0|3] ""  SBMU
 SG_ HvPwrOnCmd_SBMU14_02 : 26|2@1+ (1,0) [0|3] ""  SBMU
 SG_ HvPwrOnCmd_SBMU15_02 : 28|2@1+ (1,0) [0|3] ""  SBMU
 SG_ HvPwrOnCmd_SBMU16_02 : 30|2@1+ (1,0) [0|3] ""  SBMU
 SG_ HvPwrOnCmd_SBMU17_02 : 32|2@1+ (1,0) [0|3] ""  SBMU
 SG_ HvPwrOnCmd_SBMU18_02 : 34|2@1+ (1,0) [0|3] ""  SBMU
 SG_ HvPwrOnCmd_SBMU19_02 : 36|2@1+ (1,0) [0|3] ""  SBMU
 SG_ HvPwrOnCmd_SBMU20_02 : 38|2@1+ (1,0) [0|3] ""  SBMU
 SG_ HvPwrOnCmd_SBMU21_02 : 40|2@1+ (1,0) [0|3] ""  SBMU
 SG_ HvPwrOnCmd_SBMU22_02 : 42|2@1+ (1,0) [0|3] ""  SBMU
 SG_ HvPwrOnCmd_SBMU23_02 : 44|2@1+ (1,0) [0|3] ""  SBMU
 SG_ HvPwrOnCmd_SBMU24_02 : 46|2@1+ (1,0) [0|3] ""  SBMU
 SG_ HvPwrOnCmd_SBMU25_02 : 48|2@1+ (1,0) [0|3] ""  SBMU
 SG_ HvPwrOnCmd_SBMU26_02 : 50|2@1+ (1,0) [0|3] ""  SBMU
 SG_ HvPwrOnCmd_SBMU27_02 : 52|2@1+ (1,0) [0|3] ""  SBMU
 SG_ HvPwrOnCmd_SBMU28_02 : 54|2@1+ (1,0) [0|3] ""  SBMU
 SG_ HvPwrOnCmd_SBMU29_02 : 56|2@1+ (1,0) [0|3] ""  SBMU
 SG_ HvPwrOnCmd_SBMU30_02 : 58|2@1+ (1,0) [0|3] ""  SBMU
 SG_ HvPwrOnCmd_SBMU31_02 : 60|2@1+ (1,0) [0|3] ""  SBMU
 SG_ HvPwrOnCmd_SBMU32_02 : 62|2@1+ (1,0) [0|3] ""  SBMU

BO_ 2148630419 M2S_CMD1__03: 8 MBMU
 SG_ HvPwrOnCmd_SBMU01_03 : 0|2@1+ (1,0) [0|3] ""  SBMU
 SG_ HvPwrOnCmd_SBMU02_03 : 2|2@1+ (1,0) [0|3] ""  SBMU
 SG_ HvPwrOnCmd_SBMU03_03 : 4|2@1+ (1,0) [0|3] ""  SBMU
 SG_ HvPwrOnCmd_SBMU04_03 : 6|2@1+ (1,0) [0|3] ""  SBMU
 SG_ HvPwrOnCmd_SBMU05_03 : 8|2@1+ (1,0) [0|3] ""  SBMU
 SG_ HvPwrOnCmd_SBMU06_03 : 10|2@1+ (1,0) [0|3] ""  SBMU
 SG_ HvPwrOnCmd_SBMU07_03 : 12|2@1+ (1,0) [0|3] ""  SBMU
 SG_ HvPwrOnCmd_SBMU08_03 : 14|2@1+ (1,0) [0|3] ""  SBMU
 SG_ HvPwrOnCmd_SBMU09_03 : 16|2@1+ (1,0) [0|3] ""  SBMU
 SG_ HvPwrOnCmd_SBMU10_03 : 18|2@1+ (1,0) [0|3] ""  SBMU
 SG_ HvPwrOnCmd_SBMU11_03 : 20|2@1+ (1,0) [0|3] ""  SBMU
 SG_ HvPwrOnCmd_SBMU12_03 : 22|2@1+ (1,0) [0|3] ""  SBMU
 SG_ HvPwrOnCmd_SBMU13_03 : 24|2@1+ (1,0) [0|3] ""  SBMU
 SG_ HvPwrOnCmd_SBMU14_03 : 26|2@1+ (1,0) [0|3] ""  SBMU
 SG_ HvPwrOnCmd_SBMU15_03 : 28|2@1+ (1,0) [0|3] ""  SBMU
 SG_ HvPwrOnCmd_SBMU16_03 : 30|2@1+ (1,0) [0|3] ""  SBMU
 SG_ HvPwrOnCmd_SBMU17_03 : 32|2@1+ (1,0) [0|3] ""  SBMU
 SG_ HvPwrOnCmd_SBMU18_03 : 34|2@1+ (1,0) [0|3] ""  SBMU
 SG_ HvPwrOnCmd_SBMU19_03 : 36|2@1+ (1,0) [0|3] ""  SBMU
 SG_ HvPwrOnCmd_SBMU20_03 : 38|2@1+ (1,0) [0|3] ""  SBMU
 SG_ HvPwrOnCmd_SBMU21_03 : 40|2@1+ (1,0) [0|3] ""  SBMU
 SG_ HvPwrOnCmd_SBMU22_03 : 42|2@1+ (1,0) [0|3] ""  SBMU
 SG_ HvPwrOnCmd_SBMU23_03 : 44|2@1+ (1,0) [0|3] ""  SBMU
 SG_ HvPwrOnCmd_SBMU24_03 : 46|2@1+ (1,0) [0|3] ""  SBMU
 SG_ HvPwrOnCmd_SBMU25_03 : 48|2@1+ (1,0) [0|3] ""  SBMU
 SG_ HvPwrOnCmd_SBMU26_03 : 50|2@1+ (1,0) [0|3] ""  SBMU
 SG_ HvPwrOnCmd_SBMU27_03 : 52|2@1+ (1,0) [0|3] ""  SBMU
 SG_ HvPwrOnCmd_SBMU28_03 : 54|2@1+ (1,0) [0|3] ""  SBMU
 SG_ HvPwrOnCmd_SBMU29_03 : 56|2@1+ (1,0) [0|3] ""  SBMU
 SG_ HvPwrOnCmd_SBMU30_03 : 58|2@1+ (1,0) [0|3] ""  SBMU
 SG_ HvPwrOnCmd_SBMU31_03 : 60|2@1+ (1,0) [0|3] ""  SBMU
 SG_ HvPwrOnCmd_SBMU32_03 : 62|2@1+ (1,0) [0|3] ""  SBMU

BO_ 2148630420 M2S_CMD1__04: 8 MBMU
 SG_ HvPwrOnCmd_SBMU01_04 : 0|2@1+ (1,0) [0|3] ""  SBMU
 SG_ HvPwrOnCmd_SBMU02_04 : 2|2@1+ (1,0) [0|3] ""  SBMU
 SG_ HvPwrOnCmd_SBMU03_04 : 4|2@1+ (1,0) [0|3] ""  SBMU
 SG_ HvPwrOnCmd_SBMU04_04 : 6|2@1+ (1,0) [0|3] ""  SBMU
 SG_ HvPwrOnCmd_SBMU05_04 : 8|2@1+ (1,0) [0|3] ""  SBMU
 SG_ HvPwrOnCmd_SBMU06_04 : 10|2@1+ (1,0) [0|3] ""  SBMU
 SG_ HvPwrOnCmd_SBMU07_04 : 12|2@1+ (1,0) [0|3] ""  SBMU
 SG_ HvPwrOnCmd_SBMU08_04 : 14|2@1+ (1,0) [0|3] ""  SBMU
 SG_ HvPwrOnCmd_SBMU09_04 : 16|2@1+ (1,0) [0|3] ""  SBMU
 SG_ HvPwrOnCmd_SBMU10_04 : 18|2@1+ (1,0) [0|3] ""  SBMU
 SG_ HvPwrOnCmd_SBMU11_04 : 20|2@1+ (1,0) [0|3] ""  SBMU
 SG_ HvPwrOnCmd_SBMU12_04 : 22|2@1+ (1,0) [0|3] ""  SBMU
 SG_ HvPwrOnCmd_SBMU13_04 : 24|2@1+ (1,0) [0|3] ""  SBMU
 SG_ HvPwrOnCmd_SBMU14_04 : 26|2@1+ (1,0) [0|3] ""  SBMU
 SG_ HvPwrOnCmd_SBMU15_04 : 28|2@1+ (1,0) [0|3] ""  SBMU
 SG_ HvPwrOnCmd_SBMU16_04 : 30|2@1+ (1,0) [0|3] ""  SBMU
 SG_ HvPwrOnCmd_SBMU17_04 : 32|2@1+ (1,0) [0|3] ""  SBMU
 SG_ HvPwrOnCmd_SBMU18_04 : 34|2@1+ (1,0) [0|3] ""  SBMU
 SG_ HvPwrOnCmd_SBMU19_04 : 36|2@1+ (1,0) [0|3] ""  SBMU
 SG_ HvPwrOnCmd_SBMU20_04 : 38|2@1+ (1,0) [0|3] ""  SBMU
 SG_ HvPwrOnCmd_SBMU21_04 : 40|2@1+ (1,0) [0|3] ""  SBMU
 SG_ HvPwrOnCmd_SBMU22_04 : 42|2@1+ (1,0) [0|3] ""  SBMU
 SG_ HvPwrOnCmd_SBMU23_04 : 44|2@1+ (1,0) [0|3] ""  SBMU
 SG_ HvPwrOnCmd_SBMU24_04 : 46|2@1+ (1,0) [0|3] ""  SBMU
 SG_ HvPwrOnCmd_SBMU25_04 : 48|2@1+ (1,0) [0|3] ""  SBMU
 SG_ HvPwrOnCmd_SBMU26_04 : 50|2@1+ (1,0) [0|3] ""  SBMU
 SG_ HvPwrOnCmd_SBMU27_04 : 52|2@1+ (1,0) [0|3] ""  SBMU
 SG_ HvPwrOnCmd_SBMU28_04 : 54|2@1+ (1,0) [0|3] ""  SBMU
 SG_ HvPwrOnCmd_SBMU29_04 : 56|2@1+ (1,0) [0|3] ""  SBMU
 SG_ HvPwrOnCmd_SBMU30_04 : 58|2@1+ (1,0) [0|3] ""  SBMU
 SG_ HvPwrOnCmd_SBMU31_04 : 60|2@1+ (1,0) [0|3] ""  SBMU
 SG_ HvPwrOnCmd_SBMU32_04 : 62|2@1+ (1,0) [0|3] ""  SBMU

BO_ 2148630421 M2S_CMD1__05: 8 MBMU
 SG_ HvPwrOnCmd_SBMU01_05 : 0|2@1+ (1,0) [0|3] ""  SBMU
 SG_ HvPwrOnCmd_SBMU02_05 : 2|2@1+ (1,0) [0|3] ""  SBMU
 SG_ HvPwrOnCmd_SBMU03_05 : 4|2@1+ (1,0) [0|3] ""  SBMU
 SG_ HvPwrOnCmd_SBMU04_05 : 6|2@1+ (1,0) [0|3] ""  SBMU
 SG_ HvPwrOnCmd_SBMU05_05 : 8|2@1+ (1,0) [0|3] ""  SBMU
 SG_ HvPwrOnCmd_SBMU06_05 : 10|2@1+ (1,0) [0|3] ""  SBMU
 SG_ HvPwrOnCmd_SBMU07_05 : 12|2@1+ (1,0) [0|3] ""  SBMU
 SG_ HvPwrOnCmd_SBMU08_05 : 14|2@1+ (1,0) [0|3] ""  SBMU
 SG_ HvPwrOnCmd_SBMU09_05 : 16|2@1+ (1,0) [0|3] ""  SBMU
 SG_ HvPwrOnCmd_SBMU10_05 : 18|2@1+ (1,0) [0|3] ""  SBMU
 SG_ HvPwrOnCmd_SBMU11_05 : 20|2@1+ (1,0) [0|3] ""  SBMU
 SG_ HvPwrOnCmd_SBMU12_05 : 22|2@1+ (1,0) [0|3] ""  SBMU
 SG_ HvPwrOnCmd_SBMU13_05 : 24|2@1+ (1,0) [0|3] ""  SBMU
 SG_ HvPwrOnCmd_SBMU14_05 : 26|2@1+ (1,0) [0|3] ""  SBMU
 SG_ HvPwrOnCmd_SBMU15_05 : 28|2@1+ (1,0) [0|3] ""  SBMU
 SG_ HvPwrOnCmd_SBMU16_05 : 30|2@1+ (1,0) [0|3] ""  SBMU
 SG_ HvPwrOnCmd_SBMU17_05 : 32|2@1+ (1,0) [0|3] ""  SBMU
 SG_ HvPwrOnCmd_SBMU18_05 : 34|2@1+ (1,0) [0|3] ""  SBMU
 SG_ HvPwrOnCmd_SBMU19_05 : 36|2@1+ (1,0) [0|3] ""  SBMU
 SG_ HvPwrOnCmd_SBMU20_05 : 38|2@1+ (1,0) [0|3] ""  SBMU
 SG_ HvPwrOnCmd_SBMU21_05 : 40|2@1+ (1,0) [0|3] ""  SBMU
 SG_ HvPwrOnCmd_SBMU22_05 : 42|2@1+ (1,0) [0|3] ""  SBMU
 SG_ HvPwrOnCmd_SBMU23_05 : 44|2@1+ (1,0) [0|3] ""  SBMU
 SG_ HvPwrOnCmd_SBMU24_05 : 46|2@1+ (1,0) [0|3] ""  SBMU
 SG_ HvPwrOnCmd_SBMU25_05 : 48|2@1+ (1,0) [0|3] ""  SBMU
 SG_ HvPwrOnCmd_SBMU26_05 : 50|2@1+ (1,0) [0|3] ""  SBMU
 SG_ HvPwrOnCmd_SBMU27_05 : 52|2@1+ (1,0) [0|3] ""  SBMU
 SG_ HvPwrOnCmd_SBMU28_05 : 54|2@1+ (1,0) [0|3] ""  SBMU
 SG_ HvPwrOnCmd_SBMU29_05 : 56|2@1+ (1,0) [0|3] ""  SBMU
 SG_ HvPwrOnCmd_SBMU30_05 : 58|2@1+ (1,0) [0|3] ""  SBMU
 SG_ HvPwrOnCmd_SBMU31_05 : 60|2@1+ (1,0) [0|3] ""  SBMU
 SG_ HvPwrOnCmd_SBMU32_05 : 62|2@1+ (1,0) [0|3] ""  SBMU

BO_ 2148630422 M2S_CMD1__06: 8 MBMU
 SG_ HvPwrOnCmd_SBMU01_06 : 0|2@1+ (1,0) [0|3] ""  SBMU
 SG_ HvPwrOnCmd_SBMU02_06 : 2|2@1+ (1,0) [0|3] ""  SBMU
 SG_ HvPwrOnCmd_SBMU03_06 : 4|2@1+ (1,0) [0|3] ""  SBMU
 SG_ HvPwrOnCmd_SBMU04_06 : 6|2@1+ (1,0) [0|3] ""  SBMU
 SG_ HvPwrOnCmd_SBMU05_06 : 8|2@1+ (1,0) [0|3] ""  SBMU
 SG_ HvPwrOnCmd_SBMU06_06 : 10|2@1+ (1,0) [0|3] ""  SBMU
 SG_ HvPwrOnCmd_SBMU07_06 : 12|2@1+ (1,0) [0|3] ""  SBMU
 SG_ HvPwrOnCmd_SBMU08_06 : 14|2@1+ (1,0) [0|3] ""  SBMU
 SG_ HvPwrOnCmd_SBMU09_06 : 16|2@1+ (1,0) [0|3] ""  SBMU
 SG_ HvPwrOnCmd_SBMU10_06 : 18|2@1+ (1,0) [0|3] ""  SBMU
 SG_ HvPwrOnCmd_SBMU11_06 : 20|2@1+ (1,0) [0|3] ""  SBMU
 SG_ HvPwrOnCmd_SBMU12_06 : 22|2@1+ (1,0) [0|3] ""  SBMU
 SG_ HvPwrOnCmd_SBMU13_06 : 24|2@1+ (1,0) [0|3] ""  SBMU
 SG_ HvPwrOnCmd_SBMU14_06 : 26|2@1+ (1,0) [0|3] ""  SBMU
 SG_ HvPwrOnCmd_SBMU15_06 : 28|2@1+ (1,0) [0|3] ""  SBMU
 SG_ HvPwrOnCmd_SBMU16_06 : 30|2@1+ (1,0) [0|3] ""  SBMU
 SG_ HvPwrOnCmd_SBMU17_06 : 32|2@1+ (1,0) [0|3] ""  SBMU
 SG_ HvPwrOnCmd_SBMU18_06 : 34|2@1+ (1,0) [0|3] ""  SBMU
 SG_ HvPwrOnCmd_SBMU19_06 : 36|2@1+ (1,0) [0|3] ""  SBMU
 SG_ HvPwrOnCmd_SBMU20_06 : 38|2@1+ (1,0) [0|3] ""  SBMU
 SG_ HvPwrOnCmd_SBMU21_06 : 40|2@1+ (1,0) [0|3] ""  SBMU
 SG_ HvPwrOnCmd_SBMU22_06 : 42|2@1+ (1,0) [0|3] ""  SBMU
 SG_ HvPwrOnCmd_SBMU23_06 : 44|2@1+ (1,0) [0|3] ""  SBMU
 SG_ HvPwrOnCmd_SBMU24_06 : 46|2@1+ (1,0) [0|3] ""  SBMU
 SG_ HvPwrOnCmd_SBMU25_06 : 48|2@1+ (1,0) [0|3] ""  SBMU
 SG_ HvPwrOnCmd_SBMU26_06 : 50|2@1+ (1,0) [0|3] ""  SBMU
 SG_ HvPwrOnCmd_SBMU27_06 : 52|2@1+ (1,0) [0|3] ""  SBMU
 SG_ HvPwrOnCmd_SBMU28_06 : 54|2@1+ (1,0) [0|3] ""  SBMU
 SG_ HvPwrOnCmd_SBMU29_06 : 56|2@1+ (1,0) [0|3] ""  SBMU
 SG_ HvPwrOnCmd_SBMU30_06 : 58|2@1+ (1,0) [0|3] ""  SBMU
 SG_ HvPwrOnCmd_SBMU31_06 : 60|2@1+ (1,0) [0|3] ""  SBMU
 SG_ HvPwrOnCmd_SBMU32_06 : 62|2@1+ (1,0) [0|3] ""  SBMU

BO_ 2148630423 M2S_CMD1__07: 8 MBMU
 SG_ HvPwrOnCmd_SBMU01_07 : 0|2@1+ (1,0) [0|3] ""  SBMU
 SG_ HvPwrOnCmd_SBMU02_07 : 2|2@1+ (1,0) [0|3] ""  SBMU
 SG_ HvPwrOnCmd_SBMU03_07 : 4|2@1+ (1,0) [0|3] ""  SBMU
 SG_ HvPwrOnCmd_SBMU04_07 : 6|2@1+ (1,0) [0|3] ""  SBMU
 SG_ HvPwrOnCmd_SBMU05_07 : 8|2@1+ (1,0) [0|3] ""  SBMU
 SG_ HvPwrOnCmd_SBMU06_07 : 10|2@1+ (1,0) [0|3] ""  SBMU
 SG_ HvPwrOnCmd_SBMU07_07 : 12|2@1+ (1,0) [0|3] ""  SBMU
 SG_ HvPwrOnCmd_SBMU08_07 : 14|2@1+ (1,0) [0|3] ""  SBMU
 SG_ HvPwrOnCmd_SBMU09_07 : 16|2@1+ (1,0) [0|3] ""  SBMU
 SG_ HvPwrOnCmd_SBMU10_07 : 18|2@1+ (1,0) [0|3] ""  SBMU
 SG_ HvPwrOnCmd_SBMU11_07 : 20|2@1+ (1,0) [0|3] ""  SBMU
 SG_ HvPwrOnCmd_SBMU12_07 : 22|2@1+ (1,0) [0|3] ""  SBMU
 SG_ HvPwrOnCmd_SBMU13_07 : 24|2@1+ (1,0) [0|3] ""  SBMU
 SG_ HvPwrOnCmd_SBMU14_07 : 26|2@1+ (1,0) [0|3] ""  SBMU
 SG_ HvPwrOnCmd_SBMU15_07 : 28|2@1+ (1,0) [0|3] ""  SBMU
 SG_ HvPwrOnCmd_SBMU16_07 : 30|2@1+ (1,0) [0|3] ""  SBMU
 SG_ HvPwrOnCmd_SBMU17_07 : 32|2@1+ (1,0) [0|3] ""  SBMU
 SG_ HvPwrOnCmd_SBMU18_07 : 34|2@1+ (1,0) [0|3] ""  SBMU
 SG_ HvPwrOnCmd_SBMU19_07 : 36|2@1+ (1,0) [0|3] ""  SBMU
 SG_ HvPwrOnCmd_SBMU20_07 : 38|2@1+ (1,0) [0|3] ""  SBMU
 SG_ HvPwrOnCmd_SBMU21_07 : 40|2@1+ (1,0) [0|3] ""  SBMU
 SG_ HvPwrOnCmd_SBMU22_07 : 42|2@1+ (1,0) [0|3] ""  SBMU
 SG_ HvPwrOnCmd_SBMU23_07 : 44|2@1+ (1,0) [0|3] ""  SBMU
 SG_ HvPwrOnCmd_SBMU24_07 : 46|2@1+ (1,0) [0|3] ""  SBMU
 SG_ HvPwrOnCmd_SBMU25_07 : 48|2@1+ (1,0) [0|3] ""  SBMU
 SG_ HvPwrOnCmd_SBMU26_07 : 50|2@1+ (1,0) [0|3] ""  SBMU
 SG_ HvPwrOnCmd_SBMU27_07 : 52|2@1+ (1,0) [0|3] ""  SBMU
 SG_ HvPwrOnCmd_SBMU28_07 : 54|2@1+ (1,0) [0|3] ""  SBMU
 SG_ HvPwrOnCmd_SBMU29_07 : 56|2@1+ (1,0) [0|3] ""  SBMU
 SG_ HvPwrOnCmd_SBMU30_07 : 58|2@1+ (1,0) [0|3] ""  SBMU
 SG_ HvPwrOnCmd_SBMU31_07 : 60|2@1+ (1,0) [0|3] ""  SBMU
 SG_ HvPwrOnCmd_SBMU32_07 : 62|2@1+ (1,0) [0|3] ""  SBMU

BO_ 2148630424 M2S_CMD1__08: 8 MBMU
 SG_ HvPwrOnCmd_SBMU01_08 : 0|2@1+ (1,0) [0|3] ""  SBMU
 SG_ HvPwrOnCmd_SBMU02_08 : 2|2@1+ (1,0) [0|3] ""  SBMU
 SG_ HvPwrOnCmd_SBMU03_08 : 4|2@1+ (1,0) [0|3] ""  SBMU
 SG_ HvPwrOnCmd_SBMU04_08 : 6|2@1+ (1,0) [0|3] ""  SBMU
 SG_ HvPwrOnCmd_SBMU05_08 : 8|2@1+ (1,0) [0|3] ""  SBMU
 SG_ HvPwrOnCmd_SBMU06_08 : 10|2@1+ (1,0) [0|3] ""  SBMU
 SG_ HvPwrOnCmd_SBMU07_08 : 12|2@1+ (1,0) [0|3] ""  SBMU
 SG_ HvPwrOnCmd_SBMU08_08 : 14|2@1+ (1,0) [0|3] ""  SBMU
 SG_ HvPwrOnCmd_SBMU09_08 : 16|2@1+ (1,0) [0|3] ""  SBMU
 SG_ HvPwrOnCmd_SBMU10_08 : 18|2@1+ (1,0) [0|3] ""  SBMU
 SG_ HvPwrOnCmd_SBMU11_08 : 20|2@1+ (1,0) [0|3] ""  SBMU
 SG_ HvPwrOnCmd_SBMU12_08 : 22|2@1+ (1,0) [0|3] ""  SBMU
 SG_ HvPwrOnCmd_SBMU13_08 : 24|2@1+ (1,0) [0|3] ""  SBMU
 SG_ HvPwrOnCmd_SBMU14_08 : 26|2@1+ (1,0) [0|3] ""  SBMU
 SG_ HvPwrOnCmd_SBMU15_08 : 28|2@1+ (1,0) [0|3] ""  SBMU
 SG_ HvPwrOnCmd_SBMU16_08 : 30|2@1+ (1,0) [0|3] ""  SBMU
 SG_ HvPwrOnCmd_SBMU17_08 : 32|2@1+ (1,0) [0|3] ""  SBMU
 SG_ HvPwrOnCmd_SBMU18_08 : 34|2@1+ (1,0) [0|3] ""  SBMU
 SG_ HvPwrOnCmd_SBMU19_08 : 36|2@1+ (1,0) [0|3] ""  SBMU
 SG_ HvPwrOnCmd_SBMU20_08 : 38|2@1+ (1,0) [0|3] ""  SBMU
 SG_ HvPwrOnCmd_SBMU21_08 : 40|2@1+ (1,0) [0|3] ""  SBMU
 SG_ HvPwrOnCmd_SBMU22_08 : 42|2@1+ (1,0) [0|3] ""  SBMU
 SG_ HvPwrOnCmd_SBMU23_08 : 44|2@1+ (1,0) [0|3] ""  SBMU
 SG_ HvPwrOnCmd_SBMU24_08 : 46|2@1+ (1,0) [0|3] ""  SBMU
 SG_ HvPwrOnCmd_SBMU25_08 : 48|2@1+ (1,0) [0|3] ""  SBMU
 SG_ HvPwrOnCmd_SBMU26_08 : 50|2@1+ (1,0) [0|3] ""  SBMU
 SG_ HvPwrOnCmd_SBMU27_08 : 52|2@1+ (1,0) [0|3] ""  SBMU
 SG_ HvPwrOnCmd_SBMU28_08 : 54|2@1+ (1,0) [0|3] ""  SBMU
 SG_ HvPwrOnCmd_SBMU29_08 : 56|2@1+ (1,0) [0|3] ""  SBMU
 SG_ HvPwrOnCmd_SBMU30_08 : 58|2@1+ (1,0) [0|3] ""  SBMU
 SG_ HvPwrOnCmd_SBMU31_08 : 60|2@1+ (1,0) [0|3] ""  SBMU
 SG_ HvPwrOnCmd_SBMU32_08 : 62|2@1+ (1,0) [0|3] ""  SBMU

BO_ 2148630425 M2S_CMD1__09: 8 MBMU
 SG_ HvPwrOnCmd_SBMU01_09 : 0|2@1+ (1,0) [0|3] ""  SBMU
 SG_ HvPwrOnCmd_SBMU02_09 : 2|2@1+ (1,0) [0|3] ""  SBMU
 SG_ HvPwrOnCmd_SBMU03_09 : 4|2@1+ (1,0) [0|3] ""  SBMU
 SG_ HvPwrOnCmd_SBMU04_09 : 6|2@1+ (1,0) [0|3] ""  SBMU
 SG_ HvPwrOnCmd_SBMU05_09 : 8|2@1+ (1,0) [0|3] ""  SBMU
 SG_ HvPwrOnCmd_SBMU06_09 : 10|2@1+ (1,0) [0|3] ""  SBMU
 SG_ HvPwrOnCmd_SBMU07_09 : 12|2@1+ (1,0) [0|3] ""  SBMU
 SG_ HvPwrOnCmd_SBMU08_09 : 14|2@1+ (1,0) [0|3] ""  SBMU
 SG_ HvPwrOnCmd_SBMU09_09 : 16|2@1+ (1,0) [0|3] ""  SBMU
 SG_ HvPwrOnCmd_SBMU10_09 : 18|2@1+ (1,0) [0|3] ""  SBMU
 SG_ HvPwrOnCmd_SBMU11_09 : 20|2@1+ (1,0) [0|3] ""  SBMU
 SG_ HvPwrOnCmd_SBMU12_09 : 22|2@1+ (1,0) [0|3] ""  SBMU
 SG_ HvPwrOnCmd_SBMU13_09 : 24|2@1+ (1,0) [0|3] ""  SBMU
 SG_ HvPwrOnCmd_SBMU14_09 : 26|2@1+ (1,0) [0|3] ""  SBMU
 SG_ HvPwrOnCmd_SBMU15_09 : 28|2@1+ (1,0) [0|3] ""  SBMU
 SG_ HvPwrOnCmd_SBMU16_09 : 30|2@1+ (1,0) [0|3] ""  SBMU
 SG_ HvPwrOnCmd_SBMU17_09 : 32|2@1+ (1,0) [0|3] ""  SBMU
 SG_ HvPwrOnCmd_SBMU18_09 : 34|2@1+ (1,0) [0|3] ""  SBMU
 SG_ HvPwrOnCmd_SBMU19_09 : 36|2@1+ (1,0) [0|3] ""  SBMU
 SG_ HvPwrOnCmd_SBMU20_09 : 38|2@1+ (1,0) [0|3] ""  SBMU
 SG_ HvPwrOnCmd_SBMU21_09 : 40|2@1+ (1,0) [0|3] ""  SBMU
 SG_ HvPwrOnCmd_SBMU22_09 : 42|2@1+ (1,0) [0|3] ""  SBMU
 SG_ HvPwrOnCmd_SBMU23_09 : 44|2@1+ (1,0) [0|3] ""  SBMU
 SG_ HvPwrOnCmd_SBMU24_09 : 46|2@1+ (1,0) [0|3] ""  SBMU
 SG_ HvPwrOnCmd_SBMU25_09 : 48|2@1+ (1,0) [0|3] ""  SBMU
 SG_ HvPwrOnCmd_SBMU26_09 : 50|2@1+ (1,0) [0|3] ""  SBMU
 SG_ HvPwrOnCmd_SBMU27_09 : 52|2@1+ (1,0) [0|3] ""  SBMU
 SG_ HvPwrOnCmd_SBMU28_09 : 54|2@1+ (1,0) [0|3] ""  SBMU
 SG_ HvPwrOnCmd_SBMU29_09 : 56|2@1+ (1,0) [0|3] ""  SBMU
 SG_ HvPwrOnCmd_SBMU30_09 : 58|2@1+ (1,0) [0|3] ""  SBMU
 SG_ HvPwrOnCmd_SBMU31_09 : 60|2@1+ (1,0) [0|3] ""  SBMU
 SG_ HvPwrOnCmd_SBMU32_09 : 62|2@1+ (1,0) [0|3] ""  SBMU

BO_ 2148630426 M2S_CMD1__10: 8 MBMU
 SG_ HvPwrOnCmd_SBMU01_10 : 0|2@1+ (1,0) [0|3] ""  SBMU
 SG_ HvPwrOnCmd_SBMU02_10 : 2|2@1+ (1,0) [0|3] ""  SBMU
 SG_ HvPwrOnCmd_SBMU03_10 : 4|2@1+ (1,0) [0|3] ""  SBMU
 SG_ HvPwrOnCmd_SBMU04_10 : 6|2@1+ (1,0) [0|3] ""  SBMU
 SG_ HvPwrOnCmd_SBMU05_10 : 8|2@1+ (1,0) [0|3] ""  SBMU
 SG_ HvPwrOnCmd_SBMU06_10 : 10|2@1+ (1,0) [0|3] ""  SBMU
 SG_ HvPwrOnCmd_SBMU07_10 : 12|2@1+ (1,0) [0|3] ""  SBMU
 SG_ HvPwrOnCmd_SBMU08_10 : 14|2@1+ (1,0) [0|3] ""  SBMU
 SG_ HvPwrOnCmd_SBMU09_10 : 16|2@1+ (1,0) [0|3] ""  SBMU
 SG_ HvPwrOnCmd_SBMU10_10 : 18|2@1+ (1,0) [0|3] ""  SBMU
 SG_ HvPwrOnCmd_SBMU11_10 : 20|2@1+ (1,0) [0|3] ""  SBMU
 SG_ HvPwrOnCmd_SBMU12_10 : 22|2@1+ (1,0) [0|3] ""  SBMU
 SG_ HvPwrOnCmd_SBMU13_10 : 24|2@1+ (1,0) [0|3] ""  SBMU
 SG_ HvPwrOnCmd_SBMU14_10 : 26|2@1+ (1,0) [0|3] ""  SBMU
 SG_ HvPwrOnCmd_SBMU15_10 : 28|2@1+ (1,0) [0|3] ""  SBMU
 SG_ HvPwrOnCmd_SBMU16_10 : 30|2@1+ (1,0) [0|3] ""  SBMU
 SG_ HvPwrOnCmd_SBMU17_10 : 32|2@1+ (1,0) [0|3] ""  SBMU
 SG_ HvPwrOnCmd_SBMU18_10 : 34|2@1+ (1,0) [0|3] ""  SBMU
 SG_ HvPwrOnCmd_SBMU19_10 : 36|2@1+ (1,0) [0|3] ""  SBMU
 SG_ HvPwrOnCmd_SBMU20_10 : 38|2@1+ (1,0) [0|3] ""  SBMU
 SG_ HvPwrOnCmd_SBMU21_10 : 40|2@1+ (1,0) [0|3] ""  SBMU
 SG_ HvPwrOnCmd_SBMU22_10 : 42|2@1+ (1,0) [0|3] ""  SBMU
 SG_ HvPwrOnCmd_SBMU23_10 : 44|2@1+ (1,0) [0|3] ""  SBMU
 SG_ HvPwrOnCmd_SBMU24_10 : 46|2@1+ (1,0) [0|3] ""  SBMU
 SG_ HvPwrOnCmd_SBMU25_10 : 48|2@1+ (1,0) [0|3] ""  SBMU
 SG_ HvPwrOnCmd_SBMU26_10 : 50|2@1+ (1,0) [0|3] ""  SBMU
 SG_ HvPwrOnCmd_SBMU27_10 : 52|2@1+ (1,0) [0|3] ""  SBMU
 SG_ HvPwrOnCmd_SBMU28_10 : 54|2@1+ (1,0) [0|3] ""  SBMU
 SG_ HvPwrOnCmd_SBMU29_10 : 56|2@1+ (1,0) [0|3] ""  SBMU
 SG_ HvPwrOnCmd_SBMU30_10 : 58|2@1+ (1,0) [0|3] ""  SBMU
 SG_ HvPwrOnCmd_SBMU31_10 : 60|2@1+ (1,0) [0|3] ""  SBMU
 SG_ HvPwrOnCmd_SBMU32_10 : 62|2@1+ (1,0) [0|3] ""  SBMU

BO_ 2148630427 M2S_CMD1__11: 8 MBMU
 SG_ HvPwrOnCmd_SBMU01_11 : 0|2@1+ (1,0) [0|3] ""  SBMU
 SG_ HvPwrOnCmd_SBMU02_11 : 2|2@1+ (1,0) [0|3] ""  SBMU
 SG_ HvPwrOnCmd_SBMU03_11 : 4|2@1+ (1,0) [0|3] ""  SBMU
 SG_ HvPwrOnCmd_SBMU04_11 : 6|2@1+ (1,0) [0|3] ""  SBMU
 SG_ HvPwrOnCmd_SBMU05_11 : 8|2@1+ (1,0) [0|3] ""  SBMU
 SG_ HvPwrOnCmd_SBMU06_11 : 10|2@1+ (1,0) [0|3] ""  SBMU
 SG_ HvPwrOnCmd_SBMU07_11 : 12|2@1+ (1,0) [0|3] ""  SBMU
 SG_ HvPwrOnCmd_SBMU08_11 : 14|2@1+ (1,0) [0|3] ""  SBMU
 SG_ HvPwrOnCmd_SBMU09_11 : 16|2@1+ (1,0) [0|3] ""  SBMU
 SG_ HvPwrOnCmd_SBMU10_11 : 18|2@1+ (1,0) [0|3] ""  SBMU
 SG_ HvPwrOnCmd_SBMU11_11 : 20|2@1+ (1,0) [0|3] ""  SBMU
 SG_ HvPwrOnCmd_SBMU12_11 : 22|2@1+ (1,0) [0|3] ""  SBMU
 SG_ HvPwrOnCmd_SBMU13_11 : 24|2@1+ (1,0) [0|3] ""  SBMU
 SG_ HvPwrOnCmd_SBMU14_11 : 26|2@1+ (1,0) [0|3] ""  SBMU
 SG_ HvPwrOnCmd_SBMU15_11 : 28|2@1+ (1,0) [0|3] ""  SBMU
 SG_ HvPwrOnCmd_SBMU16_11 : 30|2@1+ (1,0) [0|3] ""  SBMU
 SG_ HvPwrOnCmd_SBMU17_11 : 32|2@1+ (1,0) [0|3] ""  SBMU
 SG_ HvPwrOnCmd_SBMU18_11 : 34|2@1+ (1,0) [0|3] ""  SBMU
 SG_ HvPwrOnCmd_SBMU19_11 : 36|2@1+ (1,0) [0|3] ""  SBMU
 SG_ HvPwrOnCmd_SBMU20_11 : 38|2@1+ (1,0) [0|3] ""  SBMU
 SG_ HvPwrOnCmd_SBMU21_11 : 40|2@1+ (1,0) [0|3] ""  SBMU
 SG_ HvPwrOnCmd_SBMU22_11 : 42|2@1+ (1,0) [0|3] ""  SBMU
 SG_ HvPwrOnCmd_SBMU23_11 : 44|2@1+ (1,0) [0|3] ""  SBMU
 SG_ HvPwrOnCmd_SBMU24_11 : 46|2@1+ (1,0) [0|3] ""  SBMU
 SG_ HvPwrOnCmd_SBMU25_11 : 48|2@1+ (1,0) [0|3] ""  SBMU
 SG_ HvPwrOnCmd_SBMU26_11 : 50|2@1+ (1,0) [0|3] ""  SBMU
 SG_ HvPwrOnCmd_SBMU27_11 : 52|2@1+ (1,0) [0|3] ""  SBMU
 SG_ HvPwrOnCmd_SBMU28_11 : 54|2@1+ (1,0) [0|3] ""  SBMU
 SG_ HvPwrOnCmd_SBMU29_11 : 56|2@1+ (1,0) [0|3] ""  SBMU
 SG_ HvPwrOnCmd_SBMU30_11 : 58|2@1+ (1,0) [0|3] ""  SBMU
 SG_ HvPwrOnCmd_SBMU31_11 : 60|2@1+ (1,0) [0|3] ""  SBMU
 SG_ HvPwrOnCmd_SBMU32_11 : 62|2@1+ (1,0) [0|3] ""  SBMU

BO_ 2148630428 M2S_CMD1__12: 8 MBMU
 SG_ HvPwrOnCmd_SBMU01_12 : 0|2@1+ (1,0) [0|3] ""  SBMU
 SG_ HvPwrOnCmd_SBMU02_12 : 2|2@1+ (1,0) [0|3] ""  SBMU
 SG_ HvPwrOnCmd_SBMU03_12 : 4|2@1+ (1,0) [0|3] ""  SBMU
 SG_ HvPwrOnCmd_SBMU04_12 : 6|2@1+ (1,0) [0|3] ""  SBMU
 SG_ HvPwrOnCmd_SBMU05_12 : 8|2@1+ (1,0) [0|3] ""  SBMU
 SG_ HvPwrOnCmd_SBMU06_12 : 10|2@1+ (1,0) [0|3] ""  SBMU
 SG_ HvPwrOnCmd_SBMU07_12 : 12|2@1+ (1,0) [0|3] ""  SBMU
 SG_ HvPwrOnCmd_SBMU08_12 : 14|2@1+ (1,0) [0|3] ""  SBMU
 SG_ HvPwrOnCmd_SBMU09_12 : 16|2@1+ (1,0) [0|3] ""  SBMU
 SG_ HvPwrOnCmd_SBMU10_12 : 18|2@1+ (1,0) [0|3] ""  SBMU
 SG_ HvPwrOnCmd_SBMU11_12 : 20|2@1+ (1,0) [0|3] ""  SBMU
 SG_ HvPwrOnCmd_SBMU12_12 : 22|2@1+ (1,0) [0|3] ""  SBMU
 SG_ HvPwrOnCmd_SBMU13_12 : 24|2@1+ (1,0) [0|3] ""  SBMU
 SG_ HvPwrOnCmd_SBMU14_12 : 26|2@1+ (1,0) [0|3] ""  SBMU
 SG_ HvPwrOnCmd_SBMU15_12 : 28|2@1+ (1,0) [0|3] ""  SBMU
 SG_ HvPwrOnCmd_SBMU16_12 : 30|2@1+ (1,0) [0|3] ""  SBMU
 SG_ HvPwrOnCmd_SBMU17_12 : 32|2@1+ (1,0) [0|3] ""  SBMU
 SG_ HvPwrOnCmd_SBMU18_12 : 34|2@1+ (1,0) [0|3] ""  SBMU
 SG_ HvPwrOnCmd_SBMU19_12 : 36|2@1+ (1,0) [0|3] ""  SBMU
 SG_ HvPwrOnCmd_SBMU20_12 : 38|2@1+ (1,0) [0|3] ""  SBMU
 SG_ HvPwrOnCmd_SBMU21_12 : 40|2@1+ (1,0) [0|3] ""  SBMU
 SG_ HvPwrOnCmd_SBMU22_12 : 42|2@1+ (1,0) [0|3] ""  SBMU
 SG_ HvPwrOnCmd_SBMU23_12 : 44|2@1+ (1,0) [0|3] ""  SBMU
 SG_ HvPwrOnCmd_SBMU24_12 : 46|2@1+ (1,0) [0|3] ""  SBMU
 SG_ HvPwrOnCmd_SBMU25_12 : 48|2@1+ (1,0) [0|3] ""  SBMU
 SG_ HvPwrOnCmd_SBMU26_12 : 50|2@1+ (1,0) [0|3] ""  SBMU
 SG_ HvPwrOnCmd_SBMU27_12 : 52|2@1+ (1,0) [0|3] ""  SBMU
 SG_ HvPwrOnCmd_SBMU28_12 : 54|2@1+ (1,0) [0|3] ""  SBMU
 SG_ HvPwrOnCmd_SBMU29_12 : 56|2@1+ (1,0) [0|3] ""  SBMU
 SG_ HvPwrOnCmd_SBMU30_12 : 58|2@1+ (1,0) [0|3] ""  SBMU
 SG_ HvPwrOnCmd_SBMU31_12 : 60|2@1+ (1,0) [0|3] ""  SBMU
 SG_ HvPwrOnCmd_SBMU32_12 : 62|2@1+ (1,0) [0|3] ""  SBMU

BO_ 2148630429 M2S_CMD1__13: 8 MBMU
 SG_ HvPwrOnCmd_SBMU01_13 : 0|2@1+ (1,0) [0|3] ""  SBMU
 SG_ HvPwrOnCmd_SBMU02_13 : 2|2@1+ (1,0) [0|3] ""  SBMU
 SG_ HvPwrOnCmd_SBMU03_13 : 4|2@1+ (1,0) [0|3] ""  SBMU
 SG_ HvPwrOnCmd_SBMU04_13 : 6|2@1+ (1,0) [0|3] ""  SBMU
 SG_ HvPwrOnCmd_SBMU05_13 : 8|2@1+ (1,0) [0|3] ""  SBMU
 SG_ HvPwrOnCmd_SBMU06_13 : 10|2@1+ (1,0) [0|3] ""  SBMU
 SG_ HvPwrOnCmd_SBMU07_13 : 12|2@1+ (1,0) [0|3] ""  SBMU
 SG_ HvPwrOnCmd_SBMU08_13 : 14|2@1+ (1,0) [0|3] ""  SBMU
 SG_ HvPwrOnCmd_SBMU09_13 : 16|2@1+ (1,0) [0|3] ""  SBMU
 SG_ HvPwrOnCmd_SBMU10_13 : 18|2@1+ (1,0) [0|3] ""  SBMU
 SG_ HvPwrOnCmd_SBMU11_13 : 20|2@1+ (1,0) [0|3] ""  SBMU
 SG_ HvPwrOnCmd_SBMU12_13 : 22|2@1+ (1,0) [0|3] ""  SBMU
 SG_ HvPwrOnCmd_SBMU13_13 : 24|2@1+ (1,0) [0|3] ""  SBMU
 SG_ HvPwrOnCmd_SBMU14_13 : 26|2@1+ (1,0) [0|3] ""  SBMU
 SG_ HvPwrOnCmd_SBMU15_13 : 28|2@1+ (1,0) [0|3] ""  SBMU
 SG_ HvPwrOnCmd_SBMU16_13 : 30|2@1+ (1,0) [0|3] ""  SBMU
 SG_ HvPwrOnCmd_SBMU17_13 : 32|2@1+ (1,0) [0|3] ""  SBMU
 SG_ HvPwrOnCmd_SBMU18_13 : 34|2@1+ (1,0) [0|3] ""  SBMU
 SG_ HvPwrOnCmd_SBMU19_13 : 36|2@1+ (1,0) [0|3] ""  SBMU
 SG_ HvPwrOnCmd_SBMU20_13 : 38|2@1+ (1,0) [0|3] ""  SBMU
 SG_ HvPwrOnCmd_SBMU21_13 : 40|2@1+ (1,0) [0|3] ""  SBMU
 SG_ HvPwrOnCmd_SBMU22_13 : 42|2@1+ (1,0) [0|3] ""  SBMU
 SG_ HvPwrOnCmd_SBMU23_13 : 44|2@1+ (1,0) [0|3] ""  SBMU
 SG_ HvPwrOnCmd_SBMU24_13 : 46|2@1+ (1,0) [0|3] ""  SBMU
 SG_ HvPwrOnCmd_SBMU25_13 : 48|2@1+ (1,0) [0|3] ""  SBMU
 SG_ HvPwrOnCmd_SBMU26_13 : 50|2@1+ (1,0) [0|3] ""  SBMU
 SG_ HvPwrOnCmd_SBMU27_13 : 52|2@1+ (1,0) [0|3] ""  SBMU
 SG_ HvPwrOnCmd_SBMU28_13 : 54|2@1+ (1,0) [0|3] ""  SBMU
 SG_ HvPwrOnCmd_SBMU29_13 : 56|2@1+ (1,0) [0|3] ""  SBMU
 SG_ HvPwrOnCmd_SBMU30_13 : 58|2@1+ (1,0) [0|3] ""  SBMU
 SG_ HvPwrOnCmd_SBMU31_13 : 60|2@1+ (1,0) [0|3] ""  SBMU
 SG_ HvPwrOnCmd_SBMU32_13 : 62|2@1+ (1,0) [0|3] ""  SBMU

BO_ 2148630430 M2S_CMD1__14: 8 MBMU
 SG_ HvPwrOnCmd_SBMU01_14 : 0|2@1+ (1,0) [0|3] ""  SBMU
 SG_ HvPwrOnCmd_SBMU02_14 : 2|2@1+ (1,0) [0|3] ""  SBMU
 SG_ HvPwrOnCmd_SBMU03_14 : 4|2@1+ (1,0) [0|3] ""  SBMU
 SG_ HvPwrOnCmd_SBMU04_14 : 6|2@1+ (1,0) [0|3] ""  SBMU
 SG_ HvPwrOnCmd_SBMU05_14 : 8|2@1+ (1,0) [0|3] ""  SBMU
 SG_ HvPwrOnCmd_SBMU06_14 : 10|2@1+ (1,0) [0|3] ""  SBMU
 SG_ HvPwrOnCmd_SBMU07_14 : 12|2@1+ (1,0) [0|3] ""  SBMU
 SG_ HvPwrOnCmd_SBMU08_14 : 14|2@1+ (1,0) [0|3] ""  SBMU
 SG_ HvPwrOnCmd_SBMU09_14 : 16|2@1+ (1,0) [0|3] ""  SBMU
 SG_ HvPwrOnCmd_SBMU10_14 : 18|2@1+ (1,0) [0|3] ""  SBMU
 SG_ HvPwrOnCmd_SBMU11_14 : 20|2@1+ (1,0) [0|3] ""  SBMU
 SG_ HvPwrOnCmd_SBMU12_14 : 22|2@1+ (1,0) [0|3] ""  SBMU
 SG_ HvPwrOnCmd_SBMU13_14 : 24|2@1+ (1,0) [0|3] ""  SBMU
 SG_ HvPwrOnCmd_SBMU14_14 : 26|2@1+ (1,0) [0|3] ""  SBMU
 SG_ HvPwrOnCmd_SBMU15_14 : 28|2@1+ (1,0) [0|3] ""  SBMU
 SG_ HvPwrOnCmd_SBMU16_14 : 30|2@1+ (1,0) [0|3] ""  SBMU
 SG_ HvPwrOnCmd_SBMU17_14 : 32|2@1+ (1,0) [0|3] ""  SBMU
 SG_ HvPwrOnCmd_SBMU18_14 : 34|2@1+ (1,0) [0|3] ""  SBMU
 SG_ HvPwrOnCmd_SBMU19_14 : 36|2@1+ (1,0) [0|3] ""  SBMU
 SG_ HvPwrOnCmd_SBMU20_14 : 38|2@1+ (1,0) [0|3] ""  SBMU
 SG_ HvPwrOnCmd_SBMU21_14 : 40|2@1+ (1,0) [0|3] ""  SBMU
 SG_ HvPwrOnCmd_SBMU22_14 : 42|2@1+ (1,0) [0|3] ""  SBMU
 SG_ HvPwrOnCmd_SBMU23_14 : 44|2@1+ (1,0) [0|3] ""  SBMU
 SG_ HvPwrOnCmd_SBMU24_14 : 46|2@1+ (1,0) [0|3] ""  SBMU
 SG_ HvPwrOnCmd_SBMU25_14 : 48|2@1+ (1,0) [0|3] ""  SBMU
 SG_ HvPwrOnCmd_SBMU26_14 : 50|2@1+ (1,0) [0|3] ""  SBMU
 SG_ HvPwrOnCmd_SBMU27_14 : 52|2@1+ (1,0) [0|3] ""  SBMU
 SG_ HvPwrOnCmd_SBMU28_14 : 54|2@1+ (1,0) [0|3] ""  SBMU
 SG_ HvPwrOnCmd_SBMU29_14 : 56|2@1+ (1,0) [0|3] ""  SBMU
 SG_ HvPwrOnCmd_SBMU30_14 : 58|2@1+ (1,0) [0|3] ""  SBMU
 SG_ HvPwrOnCmd_SBMU31_14 : 60|2@1+ (1,0) [0|3] ""  SBMU
 SG_ HvPwrOnCmd_SBMU32_14 : 62|2@1+ (1,0) [0|3] ""  SBMU

BO_ 2148630431 M2S_CMD1__15: 8 MBMU
 SG_ HvPwrOnCmd_SBMU01_15 : 0|2@1+ (1,0) [0|3] ""  SBMU
 SG_ HvPwrOnCmd_SBMU02_15 : 2|2@1+ (1,0) [0|3] ""  SBMU
 SG_ HvPwrOnCmd_SBMU03_15 : 4|2@1+ (1,0) [0|3] ""  SBMU
 SG_ HvPwrOnCmd_SBMU04_15 : 6|2@1+ (1,0) [0|3] ""  SBMU
 SG_ HvPwrOnCmd_SBMU05_15 : 8|2@1+ (1,0) [0|3] ""  SBMU
 SG_ HvPwrOnCmd_SBMU06_15 : 10|2@1+ (1,0) [0|3] ""  SBMU
 SG_ HvPwrOnCmd_SBMU07_15 : 12|2@1+ (1,0) [0|3] ""  SBMU
 SG_ HvPwrOnCmd_SBMU08_15 : 14|2@1+ (1,0) [0|3] ""  SBMU
 SG_ HvPwrOnCmd_SBMU09_15 : 16|2@1+ (1,0) [0|3] ""  SBMU
 SG_ HvPwrOnCmd_SBMU10_15 : 18|2@1+ (1,0) [0|3] ""  SBMU
 SG_ HvPwrOnCmd_SBMU11_15 : 20|2@1+ (1,0) [0|3] ""  SBMU
 SG_ HvPwrOnCmd_SBMU12_15 : 22|2@1+ (1,0) [0|3] ""  SBMU
 SG_ HvPwrOnCmd_SBMU13_15 : 24|2@1+ (1,0) [0|3] ""  SBMU
 SG_ HvPwrOnCmd_SBMU14_15 : 26|2@1+ (1,0) [0|3] ""  SBMU
 SG_ HvPwrOnCmd_SBMU15_15 : 28|2@1+ (1,0) [0|3] ""  SBMU
 SG_ HvPwrOnCmd_SBMU16_15 : 30|2@1+ (1,0) [0|3] ""  SBMU
 SG_ HvPwrOnCmd_SBMU17_15 : 32|2@1+ (1,0) [0|3] ""  SBMU
 SG_ HvPwrOnCmd_SBMU18_15 : 34|2@1+ (1,0) [0|3] ""  SBMU
 SG_ HvPwrOnCmd_SBMU19_15 : 36|2@1+ (1,0) [0|3] ""  SBMU
 SG_ HvPwrOnCmd_SBMU20_15 : 38|2@1+ (1,0) [0|3] ""  SBMU
 SG_ HvPwrOnCmd_SBMU21_15 : 40|2@1+ (1,0) [0|3] ""  SBMU
 SG_ HvPwrOnCmd_SBMU22_15 : 42|2@1+ (1,0) [0|3] ""  SBMU
 SG_ HvPwrOnCmd_SBMU23_15 : 44|2@1+ (1,0) [0|3] ""  SBMU
 SG_ HvPwrOnCmd_SBMU24_15 : 46|2@1+ (1,0) [0|3] ""  SBMU
 SG_ HvPwrOnCmd_SBMU25_15 : 48|2@1+ (1,0) [0|3] ""  SBMU
 SG_ HvPwrOnCmd_SBMU26_15 : 50|2@1+ (1,0) [0|3] ""  SBMU
 SG_ HvPwrOnCmd_SBMU27_15 : 52|2@1+ (1,0) [0|3] ""  SBMU
 SG_ HvPwrOnCmd_SBMU28_15 : 54|2@1+ (1,0) [0|3] ""  SBMU
 SG_ HvPwrOnCmd_SBMU29_15 : 56|2@1+ (1,0) [0|3] ""  SBMU
 SG_ HvPwrOnCmd_SBMU30_15 : 58|2@1+ (1,0) [0|3] ""  SBMU
 SG_ HvPwrOnCmd_SBMU31_15 : 60|2@1+ (1,0) [0|3] ""  SBMU
 SG_ HvPwrOnCmd_SBMU32_15 : 62|2@1+ (1,0) [0|3] ""  SBMU

BO_ 2148630432 M2S_CMD1__16: 8 MBMU
 SG_ HvPwrOnCmd_SBMU01_16 : 0|2@1+ (1,0) [0|3] ""  SBMU
 SG_ HvPwrOnCmd_SBMU02_16 : 2|2@1+ (1,0) [0|3] ""  SBMU
 SG_ HvPwrOnCmd_SBMU03_16 : 4|2@1+ (1,0) [0|3] ""  SBMU
 SG_ HvPwrOnCmd_SBMU04_16 : 6|2@1+ (1,0) [0|3] ""  SBMU
 SG_ HvPwrOnCmd_SBMU05_16 : 8|2@1+ (1,0) [0|3] ""  SBMU
 SG_ HvPwrOnCmd_SBMU06_16 : 10|2@1+ (1,0) [0|3] ""  SBMU
 SG_ HvPwrOnCmd_SBMU07_16 : 12|2@1+ (1,0) [0|3] ""  SBMU
 SG_ HvPwrOnCmd_SBMU08_16 : 14|2@1+ (1,0) [0|3] ""  SBMU
 SG_ HvPwrOnCmd_SBMU09_16 : 16|2@1+ (1,0) [0|3] ""  SBMU
 SG_ HvPwrOnCmd_SBMU10_16 : 18|2@1+ (1,0) [0|3] ""  SBMU
 SG_ HvPwrOnCmd_SBMU11_16 : 20|2@1+ (1,0) [0|3] ""  SBMU
 SG_ HvPwrOnCmd_SBMU12_16 : 22|2@1+ (1,0) [0|3] ""  SBMU
 SG_ HvPwrOnCmd_SBMU13_16 : 24|2@1+ (1,0) [0|3] ""  SBMU
 SG_ HvPwrOnCmd_SBMU14_16 : 26|2@1+ (1,0) [0|3] ""  SBMU
 SG_ HvPwrOnCmd_SBMU15_16 : 28|2@1+ (1,0) [0|3] ""  SBMU
 SG_ HvPwrOnCmd_SBMU16_16 : 30|2@1+ (1,0) [0|3] ""  SBMU
 SG_ HvPwrOnCmd_SBMU17_16 : 32|2@1+ (1,0) [0|3] ""  SBMU
 SG_ HvPwrOnCmd_SBMU18_16 : 34|2@1+ (1,0) [0|3] ""  SBMU
 SG_ HvPwrOnCmd_SBMU19_16 : 36|2@1+ (1,0) [0|3] ""  SBMU
 SG_ HvPwrOnCmd_SBMU20_16 : 38|2@1+ (1,0) [0|3] ""  SBMU
 SG_ HvPwrOnCmd_SBMU21_16 : 40|2@1+ (1,0) [0|3] ""  SBMU
 SG_ HvPwrOnCmd_SBMU22_16 : 42|2@1+ (1,0) [0|3] ""  SBMU
 SG_ HvPwrOnCmd_SBMU23_16 : 44|2@1+ (1,0) [0|3] ""  SBMU
 SG_ HvPwrOnCmd_SBMU24_16 : 46|2@1+ (1,0) [0|3] ""  SBMU
 SG_ HvPwrOnCmd_SBMU25_16 : 48|2@1+ (1,0) [0|3] ""  SBMU
 SG_ HvPwrOnCmd_SBMU26_16 : 50|2@1+ (1,0) [0|3] ""  SBMU
 SG_ HvPwrOnCmd_SBMU27_16 : 52|2@1+ (1,0) [0|3] ""  SBMU
 SG_ HvPwrOnCmd_SBMU28_16 : 54|2@1+ (1,0) [0|3] ""  SBMU
 SG_ HvPwrOnCmd_SBMU29_16 : 56|2@1+ (1,0) [0|3] ""  SBMU
 SG_ HvPwrOnCmd_SBMU30_16 : 58|2@1+ (1,0) [0|3] ""  SBMU
 SG_ HvPwrOnCmd_SBMU31_16 : 60|2@1+ (1,0) [0|3] ""  SBMU
 SG_ HvPwrOnCmd_SBMU32_16 : 62|2@1+ (1,0) [0|3] ""  SBMU

CM_ SG_ 2197352198 S2P_CSCVerData_Data0_06 "CSC发送的软件版本号报文字节1";
CM_ SG_ 2197352198 S2P_CSCVerData_Data1_06 "CSC发送的软件版本号报文字节2";
CM_ SG_ 2197352198 S2P_CSCVerData_Data2_06 "CSC发送的软件版本号报文字节3";
CM_ SG_ 2197352198 S2P_CSCVerData_Data3_06 "CSC发送的软件版本号报文字节4";
CM_ SG_ 2197352198 S2P_CSCVerData_Data4_06 "CSC发送的软件版本号报文字节5";
CM_ SG_ 2197352198 S2P_CSCVerData_Data5_06 "CSC发送的软件版本号报文字节6";
CM_ SG_ 2197352198 S2P_CSCVerData_Data6_06 "CSC发送的软件版本号报文字节7";
CM_ SG_ 2197352198 S2P_CSCVerData_Data7_06 "CSC发送的软件版本号报文字节8";
CM_ SG_ 2197352199 S2P_CSCVerData_Data0_07 "CSC发送的软件版本号报文字节1";
CM_ SG_ 2197352199 S2P_CSCVerData_Data1_07 "CSC发送的软件版本号报文字节2";
CM_ SG_ 2197352199 S2P_CSCVerData_Data2_07 "CSC发送的软件版本号报文字节3";
CM_ SG_ 2197352199 S2P_CSCVerData_Data3_07 "CSC发送的软件版本号报文字节4";
CM_ SG_ 2197352199 S2P_CSCVerData_Data4_07 "CSC发送的软件版本号报文字节5";
CM_ SG_ 2197352199 S2P_CSCVerData_Data5_07 "CSC发送的软件版本号报文字节6";
CM_ SG_ 2197352199 S2P_CSCVerData_Data6_07 "CSC发送的软件版本号报文字节7";
CM_ SG_ 2197352199 S2P_CSCVerData_Data7_07 "CSC发送的软件版本号报文字节8";
CM_ SG_ 2197352200 S2P_CSCVerData_Data0_08 "CSC发送的软件版本号报文字节1";
CM_ SG_ 2197352200 S2P_CSCVerData_Data1_08 "CSC发送的软件版本号报文字节2";
CM_ SG_ 2197352200 S2P_CSCVerData_Data2_08 "CSC发送的软件版本号报文字节3";
CM_ SG_ 2197352200 S2P_CSCVerData_Data3_08 "CSC发送的软件版本号报文字节4";
CM_ SG_ 2197352200 S2P_CSCVerData_Data4_08 "CSC发送的软件版本号报文字节5";
CM_ SG_ 2197352200 S2P_CSCVerData_Data5_08 "CSC发送的软件版本号报文字节6";
CM_ SG_ 2197352200 S2P_CSCVerData_Data6_08 "CSC发送的软件版本号报文字节7";
CM_ SG_ 2197352200 S2P_CSCVerData_Data7_08 "CSC发送的软件版本号报文字节8";
CM_ SG_ 2197352201 S2P_CSCVerData_Data0_09 "CSC发送的软件版本号报文字节1";
CM_ SG_ 2197352201 S2P_CSCVerData_Data1_09 "CSC发送的软件版本号报文字节2";
CM_ SG_ 2197352201 S2P_CSCVerData_Data2_09 "CSC发送的软件版本号报文字节3";
CM_ SG_ 2197352201 S2P_CSCVerData_Data3_09 "CSC发送的软件版本号报文字节4";
CM_ SG_ 2197352201 S2P_CSCVerData_Data4_09 "CSC发送的软件版本号报文字节5";
CM_ SG_ 2197352201 S2P_CSCVerData_Data5_09 "CSC发送的软件版本号报文字节6";
CM_ SG_ 2197352201 S2P_CSCVerData_Data6_09 "CSC发送的软件版本号报文字节7";
CM_ SG_ 2197352201 S2P_CSCVerData_Data7_09 "CSC发送的软件版本号报文字节8";
CM_ SG_ 2197352202 S2P_CSCVerData_Data0_10 "CSC发送的软件版本号报文字节1";
CM_ SG_ 2197352202 S2P_CSCVerData_Data1_10 "CSC发送的软件版本号报文字节2";
CM_ SG_ 2197352202 S2P_CSCVerData_Data2_10 "CSC发送的软件版本号报文字节3";
CM_ SG_ 2197352202 S2P_CSCVerData_Data3_10 "CSC发送的软件版本号报文字节4";
CM_ SG_ 2197352202 S2P_CSCVerData_Data4_10 "CSC发送的软件版本号报文字节5";
CM_ SG_ 2197352202 S2P_CSCVerData_Data5_10 "CSC发送的软件版本号报文字节6";
CM_ SG_ 2197352202 S2P_CSCVerData_Data6_10 "CSC发送的软件版本号报文字节7";
CM_ SG_ 2197352202 S2P_CSCVerData_Data7_10 "CSC发送的软件版本号报文字节8";
CM_ SG_ 2197352203 S2P_CSCVerData_Data0_11 "CSC发送的软件版本号报文字节1";
CM_ SG_ 2197352203 S2P_CSCVerData_Data1_11 "CSC发送的软件版本号报文字节2";
CM_ SG_ 2197352203 S2P_CSCVerData_Data2_11 "CSC发送的软件版本号报文字节3";
CM_ SG_ 2197352203 S2P_CSCVerData_Data3_11 "CSC发送的软件版本号报文字节4";
CM_ SG_ 2197352203 S2P_CSCVerData_Data4_11 "CSC发送的软件版本号报文字节5";
CM_ SG_ 2197352203 S2P_CSCVerData_Data5_11 "CSC发送的软件版本号报文字节6";
CM_ SG_ 2197352203 S2P_CSCVerData_Data6_11 "CSC发送的软件版本号报文字节7";
CM_ SG_ 2197352203 S2P_CSCVerData_Data7_11 "CSC发送的软件版本号报文字节8";
CM_ SG_ 2197352204 S2P_CSCVerData_Data0_12 "CSC发送的软件版本号报文字节1";
CM_ SG_ 2197352204 S2P_CSCVerData_Data1_12 "CSC发送的软件版本号报文字节2";
CM_ SG_ 2197352204 S2P_CSCVerData_Data2_12 "CSC发送的软件版本号报文字节3";
CM_ SG_ 2197352204 S2P_CSCVerData_Data3_12 "CSC发送的软件版本号报文字节4";
CM_ SG_ 2197352204 S2P_CSCVerData_Data4_12 "CSC发送的软件版本号报文字节5";
CM_ SG_ 2197352204 S2P_CSCVerData_Data5_12 "CSC发送的软件版本号报文字节6";
CM_ SG_ 2197352204 S2P_CSCVerData_Data6_12 "CSC发送的软件版本号报文字节7";
CM_ SG_ 2197352204 S2P_CSCVerData_Data7_12 "CSC发送的软件版本号报文字节8";
CM_ SG_ 2197352205 S2P_CSCVerData_Data0_13 "CSC发送的软件版本号报文字节1";
CM_ SG_ 2197352205 S2P_CSCVerData_Data1_13 "CSC发送的软件版本号报文字节2";
CM_ SG_ 2197352205 S2P_CSCVerData_Data2_13 "CSC发送的软件版本号报文字节3";
CM_ SG_ 2197352205 S2P_CSCVerData_Data3_13 "CSC发送的软件版本号报文字节4";
CM_ SG_ 2197352205 S2P_CSCVerData_Data4_13 "CSC发送的软件版本号报文字节5";
CM_ SG_ 2197352205 S2P_CSCVerData_Data5_13 "CSC发送的软件版本号报文字节6";
CM_ SG_ 2197352205 S2P_CSCVerData_Data6_13 "CSC发送的软件版本号报文字节7";
CM_ SG_ 2197352205 S2P_CSCVerData_Data7_13 "CSC发送的软件版本号报文字节8";
CM_ SG_ 2197352206 S2P_CSCVerData_Data0_14 "CSC发送的软件版本号报文字节1";
CM_ SG_ 2197352206 S2P_CSCVerData_Data1_14 "CSC发送的软件版本号报文字节2";
CM_ SG_ 2197352206 S2P_CSCVerData_Data2_14 "CSC发送的软件版本号报文字节3";
CM_ SG_ 2197352206 S2P_CSCVerData_Data3_14 "CSC发送的软件版本号报文字节4";
CM_ SG_ 2197352206 S2P_CSCVerData_Data4_14 "CSC发送的软件版本号报文字节5";
CM_ SG_ 2197352206 S2P_CSCVerData_Data5_14 "CSC发送的软件版本号报文字节6";
CM_ SG_ 2197352206 S2P_CSCVerData_Data6_14 "CSC发送的软件版本号报文字节7";
CM_ SG_ 2197352206 S2P_CSCVerData_Data7_14 "CSC发送的软件版本号报文字节8";
CM_ SG_ 2197352207 S2P_CSCVerData_Data0_15 "CSC发送的软件版本号报文字节1";
CM_ SG_ 2197352207 S2P_CSCVerData_Data1_15 "CSC发送的软件版本号报文字节2";
CM_ SG_ 2197352207 S2P_CSCVerData_Data2_15 "CSC发送的软件版本号报文字节3";
CM_ SG_ 2197352207 S2P_CSCVerData_Data3_15 "CSC发送的软件版本号报文字节4";
CM_ SG_ 2197352207 S2P_CSCVerData_Data4_15 "CSC发送的软件版本号报文字节5";
CM_ SG_ 2197352207 S2P_CSCVerData_Data5_15 "CSC发送的软件版本号报文字节6";
CM_ SG_ 2197352207 S2P_CSCVerData_Data6_15 "CSC发送的软件版本号报文字节7";
CM_ SG_ 2197352207 S2P_CSCVerData_Data7_15 "CSC发送的软件版本号报文字节8";
CM_ SG_ 2197352208 S2P_CSCVerData_Data0_16 "CSC发送的软件版本号报文字节1";
CM_ SG_ 2197352208 S2P_CSCVerData_Data1_16 "CSC发送的软件版本号报文字节2";
CM_ SG_ 2197352208 S2P_CSCVerData_Data2_16 "CSC发送的软件版本号报文字节3";
CM_ SG_ 2197352208 S2P_CSCVerData_Data3_16 "CSC发送的软件版本号报文字节4";
CM_ SG_ 2197352208 S2P_CSCVerData_Data4_16 "CSC发送的软件版本号报文字节5";
CM_ SG_ 2197352208 S2P_CSCVerData_Data5_16 "CSC发送的软件版本号报文字节6";
CM_ SG_ 2197352208 S2P_CSCVerData_Data6_16 "CSC发送的软件版本号报文字节7";
CM_ SG_ 2197352208 S2P_CSCVerData_Data7_16 "CSC发送的软件版本号报文字节8";
CM_ SG_ 2197352209 S2P_CSCVerData_Data0_17 "CSC发送的软件版本号报文字节1";
CM_ SG_ 2197352209 S2P_CSCVerData_Data1_17 "CSC发送的软件版本号报文字节2";
CM_ SG_ 2197352209 S2P_CSCVerData_Data2_17 "CSC发送的软件版本号报文字节3";
CM_ SG_ 2197352209 S2P_CSCVerData_Data3_17 "CSC发送的软件版本号报文字节4";
CM_ SG_ 2197352209 S2P_CSCVerData_Data4_17 "CSC发送的软件版本号报文字节5";
CM_ SG_ 2197352209 S2P_CSCVerData_Data5_17 "CSC发送的软件版本号报文字节6";
CM_ SG_ 2197352209 S2P_CSCVerData_Data6_17 "CSC发送的软件版本号报文字节7";
CM_ SG_ 2197352209 S2P_CSCVerData_Data7_17 "CSC发送的软件版本号报文字节8";
CM_ SG_ 2197352210 S2P_CSCVerData_Data0_18 "CSC发送的软件版本号报文字节1";
CM_ SG_ 2197352210 S2P_CSCVerData_Data1_18 "CSC发送的软件版本号报文字节2";
CM_ SG_ 2197352210 S2P_CSCVerData_Data2_18 "CSC发送的软件版本号报文字节3";
CM_ SG_ 2197352210 S2P_CSCVerData_Data3_18 "CSC发送的软件版本号报文字节4";
CM_ SG_ 2197352210 S2P_CSCVerData_Data4_18 "CSC发送的软件版本号报文字节5";
CM_ SG_ 2197352210 S2P_CSCVerData_Data5_18 "CSC发送的软件版本号报文字节6";
CM_ SG_ 2197352210 S2P_CSCVerData_Data6_18 "CSC发送的软件版本号报文字节7";
CM_ SG_ 2197352210 S2P_CSCVerData_Data7_18 "CSC发送的软件版本号报文字节8";
CM_ SG_ 2197352211 S2P_CSCVerData_Data0_19 "CSC发送的软件版本号报文字节1";
CM_ SG_ 2197352211 S2P_CSCVerData_Data1_19 "CSC发送的软件版本号报文字节2";
CM_ SG_ 2197352211 S2P_CSCVerData_Data2_19 "CSC发送的软件版本号报文字节3";
CM_ SG_ 2197352211 S2P_CSCVerData_Data3_19 "CSC发送的软件版本号报文字节4";
CM_ SG_ 2197352211 S2P_CSCVerData_Data4_19 "CSC发送的软件版本号报文字节5";
CM_ SG_ 2197352211 S2P_CSCVerData_Data5_19 "CSC发送的软件版本号报文字节6";
CM_ SG_ 2197352211 S2P_CSCVerData_Data6_19 "CSC发送的软件版本号报文字节7";
CM_ SG_ 2197352211 S2P_CSCVerData_Data7_19 "CSC发送的软件版本号报文字节8";
CM_ SG_ 2197352212 S2P_CSCVerData_Data0_20 "CSC发送的软件版本号报文字节1";
CM_ SG_ 2197352212 S2P_CSCVerData_Data1_20 "CSC发送的软件版本号报文字节2";
CM_ SG_ 2197352212 S2P_CSCVerData_Data2_20 "CSC发送的软件版本号报文字节3";
CM_ SG_ 2197352212 S2P_CSCVerData_Data3_20 "CSC发送的软件版本号报文字节4";
CM_ SG_ 2197352212 S2P_CSCVerData_Data4_20 "CSC发送的软件版本号报文字节5";
CM_ SG_ 2197352212 S2P_CSCVerData_Data5_20 "CSC发送的软件版本号报文字节6";
CM_ SG_ 2197352212 S2P_CSCVerData_Data6_20 "CSC发送的软件版本号报文字节7";
CM_ SG_ 2197352212 S2P_CSCVerData_Data7_20 "CSC发送的软件版本号报文字节8";
CM_ SG_ 2197352213 S2P_CSCVerData_Data0_21 "CSC发送的软件版本号报文字节1";
CM_ SG_ 2197352213 S2P_CSCVerData_Data1_21 "CSC发送的软件版本号报文字节2";
CM_ SG_ 2197352213 S2P_CSCVerData_Data2_21 "CSC发送的软件版本号报文字节3";
CM_ SG_ 2197352213 S2P_CSCVerData_Data3_21 "CSC发送的软件版本号报文字节4";
CM_ SG_ 2197352213 S2P_CSCVerData_Data4_21 "CSC发送的软件版本号报文字节5";
CM_ SG_ 2197352213 S2P_CSCVerData_Data5_21 "CSC发送的软件版本号报文字节6";
CM_ SG_ 2197352213 S2P_CSCVerData_Data6_21 "CSC发送的软件版本号报文字节7";
CM_ SG_ 2197352213 S2P_CSCVerData_Data7_21 "CSC发送的软件版本号报文字节8";
CM_ SG_ 2197352214 S2P_CSCVerData_Data0_22 "CSC发送的软件版本号报文字节1";
CM_ SG_ 2197352214 S2P_CSCVerData_Data1_22 "CSC发送的软件版本号报文字节2";
CM_ SG_ 2197352214 S2P_CSCVerData_Data2_22 "CSC发送的软件版本号报文字节3";
CM_ SG_ 2197352214 S2P_CSCVerData_Data3_22 "CSC发送的软件版本号报文字节4";
CM_ SG_ 2197352214 S2P_CSCVerData_Data4_22 "CSC发送的软件版本号报文字节5";
CM_ SG_ 2197352214 S2P_CSCVerData_Data5_22 "CSC发送的软件版本号报文字节6";
CM_ SG_ 2197352214 S2P_CSCVerData_Data6_22 "CSC发送的软件版本号报文字节7";
CM_ SG_ 2197352214 S2P_CSCVerData_Data7_22 "CSC发送的软件版本号报文字节8";
CM_ SG_ 2197352215 S2P_CSCVerData_Data0_23 "CSC发送的软件版本号报文字节1";
CM_ SG_ 2197352215 S2P_CSCVerData_Data1_23 "CSC发送的软件版本号报文字节2";
CM_ SG_ 2197352215 S2P_CSCVerData_Data2_23 "CSC发送的软件版本号报文字节3";
CM_ SG_ 2197352215 S2P_CSCVerData_Data3_23 "CSC发送的软件版本号报文字节4";
CM_ SG_ 2197352215 S2P_CSCVerData_Data4_23 "CSC发送的软件版本号报文字节5";
CM_ SG_ 2197352215 S2P_CSCVerData_Data5_23 "CSC发送的软件版本号报文字节6";
CM_ SG_ 2197352215 S2P_CSCVerData_Data6_23 "CSC发送的软件版本号报文字节7";
CM_ SG_ 2197352215 S2P_CSCVerData_Data7_23 "CSC发送的软件版本号报文字节8";
CM_ SG_ 2197352216 S2P_CSCVerData_Data0_24 "CSC发送的软件版本号报文字节1";
CM_ SG_ 2197352216 S2P_CSCVerData_Data1_24 "CSC发送的软件版本号报文字节2";
CM_ SG_ 2197352216 S2P_CSCVerData_Data2_24 "CSC发送的软件版本号报文字节3";
CM_ SG_ 2197352216 S2P_CSCVerData_Data3_24 "CSC发送的软件版本号报文字节4";
CM_ SG_ 2197352216 S2P_CSCVerData_Data4_24 "CSC发送的软件版本号报文字节5";
CM_ SG_ 2197352216 S2P_CSCVerData_Data5_24 "CSC发送的软件版本号报文字节6";
CM_ SG_ 2197352216 S2P_CSCVerData_Data6_24 "CSC发送的软件版本号报文字节7";
CM_ SG_ 2197352216 S2P_CSCVerData_Data7_24 "CSC发送的软件版本号报文字节8";
CM_ SG_ 2197352217 S2P_CSCVerData_Data0_25 "CSC发送的软件版本号报文字节1";
CM_ SG_ 2197352217 S2P_CSCVerData_Data1_25 "CSC发送的软件版本号报文字节2";
CM_ SG_ 2197352217 S2P_CSCVerData_Data2_25 "CSC发送的软件版本号报文字节3";
CM_ SG_ 2197352217 S2P_CSCVerData_Data3_25 "CSC发送的软件版本号报文字节4";
CM_ SG_ 2197352217 S2P_CSCVerData_Data4_25 "CSC发送的软件版本号报文字节5";
CM_ SG_ 2197352217 S2P_CSCVerData_Data5_25 "CSC发送的软件版本号报文字节6";
CM_ SG_ 2197352217 S2P_CSCVerData_Data6_25 "CSC发送的软件版本号报文字节7";
CM_ SG_ 2197352217 S2P_CSCVerData_Data7_25 "CSC发送的软件版本号报文字节8";
CM_ SG_ 2197352218 S2P_CSCVerData_Data0_26 "CSC发送的软件版本号报文字节1";
CM_ SG_ 2197352218 S2P_CSCVerData_Data1_26 "CSC发送的软件版本号报文字节2";
CM_ SG_ 2197352218 S2P_CSCVerData_Data2_26 "CSC发送的软件版本号报文字节3";
CM_ SG_ 2197352218 S2P_CSCVerData_Data3_26 "CSC发送的软件版本号报文字节4";
CM_ SG_ 2197352218 S2P_CSCVerData_Data4_26 "CSC发送的软件版本号报文字节5";
CM_ SG_ 2197352218 S2P_CSCVerData_Data5_26 "CSC发送的软件版本号报文字节6";
CM_ SG_ 2197352218 S2P_CSCVerData_Data6_26 "CSC发送的软件版本号报文字节7";
CM_ SG_ 2197352218 S2P_CSCVerData_Data7_26 "CSC发送的软件版本号报文字节8";
CM_ SG_ 2197352219 S2P_CSCVerData_Data0_27 "CSC发送的软件版本号报文字节1";
CM_ SG_ 2197352219 S2P_CSCVerData_Data1_27 "CSC发送的软件版本号报文字节2";
CM_ SG_ 2197352219 S2P_CSCVerData_Data2_27 "CSC发送的软件版本号报文字节3";
CM_ SG_ 2197352219 S2P_CSCVerData_Data3_27 "CSC发送的软件版本号报文字节4";
CM_ SG_ 2197352219 S2P_CSCVerData_Data4_27 "CSC发送的软件版本号报文字节5";
CM_ SG_ 2197352219 S2P_CSCVerData_Data5_27 "CSC发送的软件版本号报文字节6";
CM_ SG_ 2197352219 S2P_CSCVerData_Data6_27 "CSC发送的软件版本号报文字节7";
CM_ SG_ 2197352219 S2P_CSCVerData_Data7_27 "CSC发送的软件版本号报文字节8";
CM_ SG_ 2197352220 S2P_CSCVerData_Data0_28 "CSC发送的软件版本号报文字节1";
CM_ SG_ 2197352220 S2P_CSCVerData_Data1_28 "CSC发送的软件版本号报文字节2";
CM_ SG_ 2197352220 S2P_CSCVerData_Data2_28 "CSC发送的软件版本号报文字节3";
CM_ SG_ 2197352220 S2P_CSCVerData_Data3_28 "CSC发送的软件版本号报文字节4";
CM_ SG_ 2197352220 S2P_CSCVerData_Data4_28 "CSC发送的软件版本号报文字节5";
CM_ SG_ 2197352220 S2P_CSCVerData_Data5_28 "CSC发送的软件版本号报文字节6";
CM_ SG_ 2197352220 S2P_CSCVerData_Data6_28 "CSC发送的软件版本号报文字节7";
CM_ SG_ 2197352220 S2P_CSCVerData_Data7_28 "CSC发送的软件版本号报文字节8";
CM_ SG_ 2197352221 S2P_CSCVerData_Data0_29 "CSC发送的软件版本号报文字节1";
CM_ SG_ 2197352221 S2P_CSCVerData_Data1_29 "CSC发送的软件版本号报文字节2";
CM_ SG_ 2197352221 S2P_CSCVerData_Data2_29 "CSC发送的软件版本号报文字节3";
CM_ SG_ 2197352221 S2P_CSCVerData_Data3_29 "CSC发送的软件版本号报文字节4";
CM_ SG_ 2197352221 S2P_CSCVerData_Data4_29 "CSC发送的软件版本号报文字节5";
CM_ SG_ 2197352221 S2P_CSCVerData_Data5_29 "CSC发送的软件版本号报文字节6";
CM_ SG_ 2197352221 S2P_CSCVerData_Data6_29 "CSC发送的软件版本号报文字节7";
CM_ SG_ 2197352221 S2P_CSCVerData_Data7_29 "CSC发送的软件版本号报文字节8";
CM_ SG_ 2197352222 S2P_CSCVerData_Data0_30 "CSC发送的软件版本号报文字节1";
CM_ SG_ 2197352222 S2P_CSCVerData_Data1_30 "CSC发送的软件版本号报文字节2";
CM_ SG_ 2197352222 S2P_CSCVerData_Data2_30 "CSC发送的软件版本号报文字节3";
CM_ SG_ 2197352222 S2P_CSCVerData_Data3_30 "CSC发送的软件版本号报文字节4";
CM_ SG_ 2197352222 S2P_CSCVerData_Data4_30 "CSC发送的软件版本号报文字节5";
CM_ SG_ 2197352222 S2P_CSCVerData_Data5_30 "CSC发送的软件版本号报文字节6";
CM_ SG_ 2197352222 S2P_CSCVerData_Data6_30 "CSC发送的软件版本号报文字节7";
CM_ SG_ 2197352222 S2P_CSCVerData_Data7_30 "CSC发送的软件版本号报文字节8";
CM_ SG_ 2197352223 S2P_CSCVerData_Data0_31 "CSC发送的软件版本号报文字节1";
CM_ SG_ 2197352223 S2P_CSCVerData_Data1_31 "CSC发送的软件版本号报文字节2";
CM_ SG_ 2197352223 S2P_CSCVerData_Data2_31 "CSC发送的软件版本号报文字节3";
CM_ SG_ 2197352223 S2P_CSCVerData_Data3_31 "CSC发送的软件版本号报文字节4";
CM_ SG_ 2197352223 S2P_CSCVerData_Data4_31 "CSC发送的软件版本号报文字节5";
CM_ SG_ 2197352223 S2P_CSCVerData_Data5_31 "CSC发送的软件版本号报文字节6";
CM_ SG_ 2197352223 S2P_CSCVerData_Data6_31 "CSC发送的软件版本号报文字节7";
CM_ SG_ 2197352223 S2P_CSCVerData_Data7_31 "CSC发送的软件版本号报文字节8";
CM_ SG_ 2197679873 S2P_CSCWriteOK_Data0_01 "发送页数写入确认数据帧报文字节1";
CM_ SG_ 2197679873 S2P_CSCWriteOK_Data1_01 "发送页数写入确认数据帧报文字节2";
CM_ SG_ 2197679873 S2P_CSCWriteOK_Data2_01 "发送页数写入确认数据帧报文字节3";
CM_ SG_ 2197679873 S2P_CSCWriteOK_Data3_01 "发送页数写入确认数据帧报文字节4";
CM_ SG_ 2197679873 S2P_CSCWriteOK_Data4_01 "发送页数写入确认数据帧报文字节5";
CM_ SG_ 2197679873 S2P_CSCWriteOK_Data5_01 "发送页数写入确认数据帧报文字节6";
CM_ SG_ 2197679873 S2P_CSCWriteOK_Data6_01 "发送页数写入确认数据帧报文字节7";
CM_ SG_ 2197679873 S2P_CSCWriteOK_Data7_01 "发送页数写入确认数据帧报文字节8";
CM_ SG_ 2197679874 S2P_CSCWriteOK_Data0_02 "发送页数写入确认数据帧报文字节1";
CM_ SG_ 2197679874 S2P_CSCWriteOK_Data1_02 "发送页数写入确认数据帧报文字节2";
CM_ SG_ 2197679874 S2P_CSCWriteOK_Data2_02 "发送页数写入确认数据帧报文字节3";
CM_ SG_ 2197679874 S2P_CSCWriteOK_Data3_02 "发送页数写入确认数据帧报文字节4";
CM_ SG_ 2197679874 S2P_CSCWriteOK_Data4_02 "发送页数写入确认数据帧报文字节5";
CM_ SG_ 2197679874 S2P_CSCWriteOK_Data5_02 "发送页数写入确认数据帧报文字节6";
CM_ SG_ 2197679874 S2P_CSCWriteOK_Data6_02 "发送页数写入确认数据帧报文字节7";
CM_ SG_ 2197679874 S2P_CSCWriteOK_Data7_02 "发送页数写入确认数据帧报文字节8";
CM_ SG_ 2197679875 S2P_CSCWriteOK_Data0_03 "发送页数写入确认数据帧报文字节1";
CM_ SG_ 2197679875 S2P_CSCWriteOK_Data1_03 "发送页数写入确认数据帧报文字节2";
CM_ SG_ 2197679875 S2P_CSCWriteOK_Data2_03 "发送页数写入确认数据帧报文字节3";
CM_ SG_ 2197679875 S2P_CSCWriteOK_Data3_03 "发送页数写入确认数据帧报文字节4";
CM_ SG_ 2197679875 S2P_CSCWriteOK_Data4_03 "发送页数写入确认数据帧报文字节5";
CM_ SG_ 2197679875 S2P_CSCWriteOK_Data5_03 "发送页数写入确认数据帧报文字节6";
CM_ SG_ 2197679875 S2P_CSCWriteOK_Data6_03 "发送页数写入确认数据帧报文字节7";
CM_ SG_ 2197679875 S2P_CSCWriteOK_Data7_03 "发送页数写入确认数据帧报文字节8";
CM_ SG_ 2197679876 S2P_CSCWriteOK_Data0_04 "发送页数写入确认数据帧报文字节1";
CM_ SG_ 2197679876 S2P_CSCWriteOK_Data1_04 "发送页数写入确认数据帧报文字节2";
CM_ SG_ 2197679876 S2P_CSCWriteOK_Data2_04 "发送页数写入确认数据帧报文字节3";
CM_ SG_ 2197679876 S2P_CSCWriteOK_Data3_04 "发送页数写入确认数据帧报文字节4";
CM_ SG_ 2197679876 S2P_CSCWriteOK_Data4_04 "发送页数写入确认数据帧报文字节5";
CM_ SG_ 2197679876 S2P_CSCWriteOK_Data5_04 "发送页数写入确认数据帧报文字节6";
CM_ SG_ 2197679876 S2P_CSCWriteOK_Data6_04 "发送页数写入确认数据帧报文字节7";
CM_ SG_ 2197679876 S2P_CSCWriteOK_Data7_04 "发送页数写入确认数据帧报文字节8";
CM_ SG_ 2197679877 S2P_CSCWriteOK_Data0_05 "发送页数写入确认数据帧报文字节1";
CM_ SG_ 2197679877 S2P_CSCWriteOK_Data1_05 "发送页数写入确认数据帧报文字节2";
CM_ SG_ 2197679877 S2P_CSCWriteOK_Data2_05 "发送页数写入确认数据帧报文字节3";
CM_ SG_ 2197679877 S2P_CSCWriteOK_Data3_05 "发送页数写入确认数据帧报文字节4";
CM_ SG_ 2197679877 S2P_CSCWriteOK_Data4_05 "发送页数写入确认数据帧报文字节5";
CM_ SG_ 2197679877 S2P_CSCWriteOK_Data5_05 "发送页数写入确认数据帧报文字节6";
CM_ SG_ 2197679877 S2P_CSCWriteOK_Data6_05 "发送页数写入确认数据帧报文字节7";
CM_ SG_ 2197679877 S2P_CSCWriteOK_Data7_05 "发送页数写入确认数据帧报文字节8";
CM_ SG_ 2197679878 S2P_CSCWriteOK_Data0_06 "发送页数写入确认数据帧报文字节1";
CM_ SG_ 2197679878 S2P_CSCWriteOK_Data1_06 "发送页数写入确认数据帧报文字节2";
CM_ SG_ 2197679878 S2P_CSCWriteOK_Data2_06 "发送页数写入确认数据帧报文字节3";
CM_ SG_ 2197679878 S2P_CSCWriteOK_Data3_06 "发送页数写入确认数据帧报文字节4";
CM_ SG_ 2197679878 S2P_CSCWriteOK_Data4_06 "发送页数写入确认数据帧报文字节5";
CM_ SG_ 2197679878 S2P_CSCWriteOK_Data5_06 "发送页数写入确认数据帧报文字节6";
CM_ SG_ 2197679878 S2P_CSCWriteOK_Data6_06 "发送页数写入确认数据帧报文字节7";
CM_ SG_ 2197679878 S2P_CSCWriteOK_Data7_06 "发送页数写入确认数据帧报文字节8";
CM_ SG_ 2197679879 S2P_CSCWriteOK_Data0_07 "发送页数写入确认数据帧报文字节1";
CM_ SG_ 2197679879 S2P_CSCWriteOK_Data1_07 "发送页数写入确认数据帧报文字节2";
CM_ SG_ 2197679879 S2P_CSCWriteOK_Data2_07 "发送页数写入确认数据帧报文字节3";
CM_ SG_ 2197679879 S2P_CSCWriteOK_Data3_07 "发送页数写入确认数据帧报文字节4";
CM_ SG_ 2197679879 S2P_CSCWriteOK_Data4_07 "发送页数写入确认数据帧报文字节5";
CM_ SG_ 2197679879 S2P_CSCWriteOK_Data5_07 "发送页数写入确认数据帧报文字节6";
CM_ SG_ 2197679879 S2P_CSCWriteOK_Data6_07 "发送页数写入确认数据帧报文字节7";
CM_ SG_ 2197679879 S2P_CSCWriteOK_Data7_07 "发送页数写入确认数据帧报文字节8";
CM_ SG_ 2197679880 S2P_CSCWriteOK_Data0_08 "发送页数写入确认数据帧报文字节1";
CM_ SG_ 2197679880 S2P_CSCWriteOK_Data1_08 "发送页数写入确认数据帧报文字节2";
CM_ SG_ 2197679880 S2P_CSCWriteOK_Data2_08 "发送页数写入确认数据帧报文字节3";
CM_ SG_ 2197679880 S2P_CSCWriteOK_Data3_08 "发送页数写入确认数据帧报文字节4";
CM_ SG_ 2197679880 S2P_CSCWriteOK_Data4_08 "发送页数写入确认数据帧报文字节5";
CM_ SG_ 2197679880 S2P_CSCWriteOK_Data5_08 "发送页数写入确认数据帧报文字节6";
CM_ SG_ 2197679880 S2P_CSCWriteOK_Data6_08 "发送页数写入确认数据帧报文字节7";
CM_ SG_ 2197679880 S2P_CSCWriteOK_Data7_08 "发送页数写入确认数据帧报文字节8";
CM_ SG_ 2197679881 S2P_CSCWriteOK_Data0_09 "发送页数写入确认数据帧报文字节1";
CM_ SG_ 2197679881 S2P_CSCWriteOK_Data1_09 "发送页数写入确认数据帧报文字节2";
CM_ SG_ 2197679881 S2P_CSCWriteOK_Data2_09 "发送页数写入确认数据帧报文字节3";
CM_ SG_ 2197679881 S2P_CSCWriteOK_Data3_09 "发送页数写入确认数据帧报文字节4";
CM_ SG_ 2197679881 S2P_CSCWriteOK_Data4_09 "发送页数写入确认数据帧报文字节5";
CM_ SG_ 2197679881 S2P_CSCWriteOK_Data5_09 "发送页数写入确认数据帧报文字节6";
CM_ SG_ 2197679881 S2P_CSCWriteOK_Data6_09 "发送页数写入确认数据帧报文字节7";
CM_ SG_ 2197679881 S2P_CSCWriteOK_Data7_09 "发送页数写入确认数据帧报文字节8";
CM_ SG_ 2197679882 S2P_CSCWriteOK_Data0_10 "发送页数写入确认数据帧报文字节1";
CM_ SG_ 2197679882 S2P_CSCWriteOK_Data1_10 "发送页数写入确认数据帧报文字节2";
CM_ SG_ 2197679882 S2P_CSCWriteOK_Data2_10 "发送页数写入确认数据帧报文字节3";
CM_ SG_ 2197679882 S2P_CSCWriteOK_Data3_10 "发送页数写入确认数据帧报文字节4";
CM_ SG_ 2197679882 S2P_CSCWriteOK_Data4_10 "发送页数写入确认数据帧报文字节5";
CM_ SG_ 2197679882 S2P_CSCWriteOK_Data5_10 "发送页数写入确认数据帧报文字节6";
CM_ SG_ 2197679882 S2P_CSCWriteOK_Data6_10 "发送页数写入确认数据帧报文字节7";
CM_ SG_ 2197679882 S2P_CSCWriteOK_Data7_10 "发送页数写入确认数据帧报文字节8";
CM_ SG_ 2197679883 S2P_CSCWriteOK_Data0_11 "发送页数写入确认数据帧报文字节1";
CM_ SG_ 2197679883 S2P_CSCWriteOK_Data1_11 "发送页数写入确认数据帧报文字节2";
CM_ SG_ 2197679883 S2P_CSCWriteOK_Data2_11 "发送页数写入确认数据帧报文字节3";
CM_ SG_ 2197679883 S2P_CSCWriteOK_Data3_11 "发送页数写入确认数据帧报文字节4";
CM_ SG_ 2197679883 S2P_CSCWriteOK_Data4_11 "发送页数写入确认数据帧报文字节5";
CM_ SG_ 2197679883 S2P_CSCWriteOK_Data5_11 "发送页数写入确认数据帧报文字节6";
CM_ SG_ 2197679883 S2P_CSCWriteOK_Data6_11 "发送页数写入确认数据帧报文字节7";
CM_ SG_ 2197679883 S2P_CSCWriteOK_Data7_11 "发送页数写入确认数据帧报文字节8";
CM_ SG_ 2197679884 S2P_CSCWriteOK_Data0_12 "发送页数写入确认数据帧报文字节1";
CM_ SG_ 2197679884 S2P_CSCWriteOK_Data1_12 "发送页数写入确认数据帧报文字节2";
CM_ SG_ 2197679884 S2P_CSCWriteOK_Data2_12 "发送页数写入确认数据帧报文字节3";
CM_ SG_ 2197679884 S2P_CSCWriteOK_Data3_12 "发送页数写入确认数据帧报文字节4";
CM_ SG_ 2197679884 S2P_CSCWriteOK_Data4_12 "发送页数写入确认数据帧报文字节5";
CM_ SG_ 2197679884 S2P_CSCWriteOK_Data5_12 "发送页数写入确认数据帧报文字节6";
CM_ SG_ 2197679884 S2P_CSCWriteOK_Data6_12 "发送页数写入确认数据帧报文字节7";
CM_ SG_ 2197679884 S2P_CSCWriteOK_Data7_12 "发送页数写入确认数据帧报文字节8";
CM_ SG_ 2197679885 S2P_CSCWriteOK_Data0_13 "发送页数写入确认数据帧报文字节1";
CM_ SG_ 2197679885 S2P_CSCWriteOK_Data1_13 "发送页数写入确认数据帧报文字节2";
CM_ SG_ 2197679885 S2P_CSCWriteOK_Data2_13 "发送页数写入确认数据帧报文字节3";
CM_ SG_ 2197679885 S2P_CSCWriteOK_Data3_13 "发送页数写入确认数据帧报文字节4";
CM_ SG_ 2197679885 S2P_CSCWriteOK_Data4_13 "发送页数写入确认数据帧报文字节5";
CM_ SG_ 2197679885 S2P_CSCWriteOK_Data5_13 "发送页数写入确认数据帧报文字节6";
CM_ SG_ 2197679885 S2P_CSCWriteOK_Data6_13 "发送页数写入确认数据帧报文字节7";
CM_ SG_ 2197679885 S2P_CSCWriteOK_Data7_13 "发送页数写入确认数据帧报文字节8";
CM_ SG_ 2197679886 S2P_CSCWriteOK_Data0_14 "发送页数写入确认数据帧报文字节1";
CM_ SG_ 2197679886 S2P_CSCWriteOK_Data1_14 "发送页数写入确认数据帧报文字节2";
CM_ SG_ 2197679886 S2P_CSCWriteOK_Data2_14 "发送页数写入确认数据帧报文字节3";
CM_ SG_ 2197679886 S2P_CSCWriteOK_Data3_14 "发送页数写入确认数据帧报文字节4";
CM_ SG_ 2197679886 S2P_CSCWriteOK_Data4_14 "发送页数写入确认数据帧报文字节5";
CM_ SG_ 2197679886 S2P_CSCWriteOK_Data5_14 "发送页数写入确认数据帧报文字节6";
CM_ SG_ 2197679886 S2P_CSCWriteOK_Data6_14 "发送页数写入确认数据帧报文字节7";
CM_ SG_ 2197679886 S2P_CSCWriteOK_Data7_14 "发送页数写入确认数据帧报文字节8";
CM_ SG_ 2197679887 S2P_CSCWriteOK_Data0_15 "发送页数写入确认数据帧报文字节1";
CM_ SG_ 2197679887 S2P_CSCWriteOK_Data1_15 "发送页数写入确认数据帧报文字节2";
CM_ SG_ 2197679887 S2P_CSCWriteOK_Data2_15 "发送页数写入确认数据帧报文字节3";
CM_ SG_ 2197679887 S2P_CSCWriteOK_Data3_15 "发送页数写入确认数据帧报文字节4";
CM_ SG_ 2197679887 S2P_CSCWriteOK_Data4_15 "发送页数写入确认数据帧报文字节5";
CM_ SG_ 2197679887 S2P_CSCWriteOK_Data5_15 "发送页数写入确认数据帧报文字节6";
CM_ SG_ 2197679887 S2P_CSCWriteOK_Data6_15 "发送页数写入确认数据帧报文字节7";
CM_ SG_ 2197679887 S2P_CSCWriteOK_Data7_15 "发送页数写入确认数据帧报文字节8";
CM_ SG_ 2197679888 S2P_CSCWriteOK_Data0_16 "发送页数写入确认数据帧报文字节1";
CM_ SG_ 2197679888 S2P_CSCWriteOK_Data1_16 "发送页数写入确认数据帧报文字节2";
CM_ SG_ 2197679888 S2P_CSCWriteOK_Data2_16 "发送页数写入确认数据帧报文字节3";
CM_ SG_ 2197679888 S2P_CSCWriteOK_Data3_16 "发送页数写入确认数据帧报文字节4";
CM_ SG_ 2197679888 S2P_CSCWriteOK_Data4_16 "发送页数写入确认数据帧报文字节5";
CM_ SG_ 2197679888 S2P_CSCWriteOK_Data5_16 "发送页数写入确认数据帧报文字节6";
CM_ SG_ 2197679888 S2P_CSCWriteOK_Data6_16 "发送页数写入确认数据帧报文字节7";
CM_ SG_ 2197679888 S2P_CSCWriteOK_Data7_16 "发送页数写入确认数据帧报文字节8";
CM_ SG_ 2197679889 S2P_CSCWriteOK_Data0_17 "发送页数写入确认数据帧报文字节1";
CM_ SG_ 2197679889 S2P_CSCWriteOK_Data1_17 "发送页数写入确认数据帧报文字节2";
CM_ SG_ 2197679889 S2P_CSCWriteOK_Data2_17 "发送页数写入确认数据帧报文字节3";
CM_ SG_ 2197679889 S2P_CSCWriteOK_Data3_17 "发送页数写入确认数据帧报文字节4";
CM_ SG_ 2197679889 S2P_CSCWriteOK_Data4_17 "发送页数写入确认数据帧报文字节5";
CM_ SG_ 2197679889 S2P_CSCWriteOK_Data5_17 "发送页数写入确认数据帧报文字节6";
CM_ SG_ 2197679889 S2P_CSCWriteOK_Data6_17 "发送页数写入确认数据帧报文字节7";
CM_ SG_ 2197679889 S2P_CSCWriteOK_Data7_17 "发送页数写入确认数据帧报文字节8";
CM_ SG_ 2197679890 S2P_CSCWriteOK_Data0_18 "发送页数写入确认数据帧报文字节1";
CM_ SG_ 2197679890 S2P_CSCWriteOK_Data1_18 "发送页数写入确认数据帧报文字节2";
CM_ SG_ 2197679890 S2P_CSCWriteOK_Data2_18 "发送页数写入确认数据帧报文字节3";
CM_ SG_ 2197679890 S2P_CSCWriteOK_Data3_18 "发送页数写入确认数据帧报文字节4";
CM_ SG_ 2197679890 S2P_CSCWriteOK_Data4_18 "发送页数写入确认数据帧报文字节5";
CM_ SG_ 2197679890 S2P_CSCWriteOK_Data5_18 "发送页数写入确认数据帧报文字节6";
CM_ SG_ 2197679890 S2P_CSCWriteOK_Data6_18 "发送页数写入确认数据帧报文字节7";
CM_ SG_ 2197679890 S2P_CSCWriteOK_Data7_18 "发送页数写入确认数据帧报文字节8";
CM_ SG_ 2197679891 S2P_CSCWriteOK_Data0_19 "发送页数写入确认数据帧报文字节1";
CM_ SG_ 2197679891 S2P_CSCWriteOK_Data1_19 "发送页数写入确认数据帧报文字节2";
CM_ SG_ 2197679891 S2P_CSCWriteOK_Data2_19 "发送页数写入确认数据帧报文字节3";
CM_ SG_ 2197679891 S2P_CSCWriteOK_Data3_19 "发送页数写入确认数据帧报文字节4";
CM_ SG_ 2197679891 S2P_CSCWriteOK_Data4_19 "发送页数写入确认数据帧报文字节5";
CM_ SG_ 2197679891 S2P_CSCWriteOK_Data5_19 "发送页数写入确认数据帧报文字节6";
CM_ SG_ 2197679891 S2P_CSCWriteOK_Data6_19 "发送页数写入确认数据帧报文字节7";
CM_ SG_ 2197679891 S2P_CSCWriteOK_Data7_19 "发送页数写入确认数据帧报文字节8";
CM_ SG_ 2197679892 S2P_CSCWriteOK_Data0_20 "发送页数写入确认数据帧报文字节1";
CM_ SG_ 2197679892 S2P_CSCWriteOK_Data1_20 "发送页数写入确认数据帧报文字节2";
CM_ SG_ 2197679892 S2P_CSCWriteOK_Data2_20 "发送页数写入确认数据帧报文字节3";
CM_ SG_ 2197679892 S2P_CSCWriteOK_Data3_20 "发送页数写入确认数据帧报文字节4";
CM_ SG_ 2197679892 S2P_CSCWriteOK_Data4_20 "发送页数写入确认数据帧报文字节5";
CM_ SG_ 2197679892 S2P_CSCWriteOK_Data5_20 "发送页数写入确认数据帧报文字节6";
CM_ SG_ 2197679892 S2P_CSCWriteOK_Data6_20 "发送页数写入确认数据帧报文字节7";
CM_ SG_ 2197679892 S2P_CSCWriteOK_Data7_20 "发送页数写入确认数据帧报文字节8";
CM_ SG_ 2197679893 S2P_CSCWriteOK_Data0_21 "发送页数写入确认数据帧报文字节1";
CM_ SG_ 2197679893 S2P_CSCWriteOK_Data1_21 "发送页数写入确认数据帧报文字节2";
CM_ SG_ 2197679893 S2P_CSCWriteOK_Data2_21 "发送页数写入确认数据帧报文字节3";
CM_ SG_ 2197679893 S2P_CSCWriteOK_Data3_21 "发送页数写入确认数据帧报文字节4";
CM_ SG_ 2197679893 S2P_CSCWriteOK_Data4_21 "发送页数写入确认数据帧报文字节5";
CM_ SG_ 2197679893 S2P_CSCWriteOK_Data5_21 "发送页数写入确认数据帧报文字节6";
CM_ SG_ 2197679893 S2P_CSCWriteOK_Data6_21 "发送页数写入确认数据帧报文字节7";
CM_ SG_ 2197679893 S2P_CSCWriteOK_Data7_21 "发送页数写入确认数据帧报文字节8";
CM_ SG_ 2197679894 S2P_CSCWriteOK_Data0_22 "发送页数写入确认数据帧报文字节1";
CM_ SG_ 2197679894 S2P_CSCWriteOK_Data1_22 "发送页数写入确认数据帧报文字节2";
CM_ SG_ 2197679894 S2P_CSCWriteOK_Data2_22 "发送页数写入确认数据帧报文字节3";
CM_ SG_ 2197679894 S2P_CSCWriteOK_Data3_22 "发送页数写入确认数据帧报文字节4";
CM_ SG_ 2197679894 S2P_CSCWriteOK_Data4_22 "发送页数写入确认数据帧报文字节5";
CM_ SG_ 2197679894 S2P_CSCWriteOK_Data5_22 "发送页数写入确认数据帧报文字节6";
CM_ SG_ 2197679894 S2P_CSCWriteOK_Data6_22 "发送页数写入确认数据帧报文字节7";
CM_ SG_ 2197679894 S2P_CSCWriteOK_Data7_22 "发送页数写入确认数据帧报文字节8";
CM_ SG_ 2197679895 S2P_CSCWriteOK_Data0_23 "发送页数写入确认数据帧报文字节1";
CM_ SG_ 2197679895 S2P_CSCWriteOK_Data1_23 "发送页数写入确认数据帧报文字节2";
CM_ SG_ 2197679895 S2P_CSCWriteOK_Data2_23 "发送页数写入确认数据帧报文字节3";
CM_ SG_ 2197679895 S2P_CSCWriteOK_Data3_23 "发送页数写入确认数据帧报文字节4";
CM_ SG_ 2197679895 S2P_CSCWriteOK_Data4_23 "发送页数写入确认数据帧报文字节5";
CM_ SG_ 2197679895 S2P_CSCWriteOK_Data5_23 "发送页数写入确认数据帧报文字节6";
CM_ SG_ 2197679895 S2P_CSCWriteOK_Data6_23 "发送页数写入确认数据帧报文字节7";
CM_ SG_ 2197679895 S2P_CSCWriteOK_Data7_23 "发送页数写入确认数据帧报文字节8";
CM_ SG_ 2197679896 S2P_CSCWriteOK_Data0_24 "发送页数写入确认数据帧报文字节1";
CM_ SG_ 2197679896 S2P_CSCWriteOK_Data1_24 "发送页数写入确认数据帧报文字节2";
CM_ SG_ 2197679896 S2P_CSCWriteOK_Data2_24 "发送页数写入确认数据帧报文字节3";
CM_ SG_ 2197679896 S2P_CSCWriteOK_Data3_24 "发送页数写入确认数据帧报文字节4";
CM_ SG_ 2197679896 S2P_CSCWriteOK_Data4_24 "发送页数写入确认数据帧报文字节5";
CM_ SG_ 2197679896 S2P_CSCWriteOK_Data5_24 "发送页数写入确认数据帧报文字节6";
CM_ SG_ 2197679896 S2P_CSCWriteOK_Data6_24 "发送页数写入确认数据帧报文字节7";
CM_ SG_ 2197679896 S2P_CSCWriteOK_Data7_24 "发送页数写入确认数据帧报文字节8";
CM_ SG_ 2197679897 S2P_CSCWriteOK_Data0_25 "发送页数写入确认数据帧报文字节1";
CM_ SG_ 2197679897 S2P_CSCWriteOK_Data1_25 "发送页数写入确认数据帧报文字节2";
CM_ SG_ 2197679897 S2P_CSCWriteOK_Data2_25 "发送页数写入确认数据帧报文字节3";
CM_ SG_ 2197679897 S2P_CSCWriteOK_Data3_25 "发送页数写入确认数据帧报文字节4";
CM_ SG_ 2197679897 S2P_CSCWriteOK_Data4_25 "发送页数写入确认数据帧报文字节5";
CM_ SG_ 2197679897 S2P_CSCWriteOK_Data5_25 "发送页数写入确认数据帧报文字节6";
CM_ SG_ 2197679897 S2P_CSCWriteOK_Data6_25 "发送页数写入确认数据帧报文字节7";
CM_ SG_ 2197679897 S2P_CSCWriteOK_Data7_25 "发送页数写入确认数据帧报文字节8";
CM_ SG_ 2197679898 S2P_CSCWriteOK_Data0_26 "发送页数写入确认数据帧报文字节1";
CM_ SG_ 2197679898 S2P_CSCWriteOK_Data1_26 "发送页数写入确认数据帧报文字节2";
CM_ SG_ 2197679898 S2P_CSCWriteOK_Data2_26 "发送页数写入确认数据帧报文字节3";
CM_ SG_ 2197679898 S2P_CSCWriteOK_Data3_26 "发送页数写入确认数据帧报文字节4";
CM_ SG_ 2197679898 S2P_CSCWriteOK_Data4_26 "发送页数写入确认数据帧报文字节5";
CM_ SG_ 2197679898 S2P_CSCWriteOK_Data5_26 "发送页数写入确认数据帧报文字节6";
CM_ SG_ 2197679898 S2P_CSCWriteOK_Data6_26 "发送页数写入确认数据帧报文字节7";
CM_ SG_ 2197679898 S2P_CSCWriteOK_Data7_26 "发送页数写入确认数据帧报文字节8";
CM_ SG_ 2197679899 S2P_CSCWriteOK_Data0_27 "发送页数写入确认数据帧报文字节1";
CM_ SG_ 2197679899 S2P_CSCWriteOK_Data1_27 "发送页数写入确认数据帧报文字节2";
CM_ SG_ 2197679899 S2P_CSCWriteOK_Data2_27 "发送页数写入确认数据帧报文字节3";
CM_ SG_ 2197679899 S2P_CSCWriteOK_Data3_27 "发送页数写入确认数据帧报文字节4";
CM_ SG_ 2197679899 S2P_CSCWriteOK_Data4_27 "发送页数写入确认数据帧报文字节5";
CM_ SG_ 2197679899 S2P_CSCWriteOK_Data5_27 "发送页数写入确认数据帧报文字节6";
CM_ SG_ 2197679899 S2P_CSCWriteOK_Data6_27 "发送页数写入确认数据帧报文字节7";
CM_ SG_ 2197679899 S2P_CSCWriteOK_Data7_27 "发送页数写入确认数据帧报文字节8";
CM_ SG_ 2197679900 S2P_CSCWriteOK_Data0_28 "发送页数写入确认数据帧报文字节1";
CM_ SG_ 2197679900 S2P_CSCWriteOK_Data1_28 "发送页数写入确认数据帧报文字节2";
CM_ SG_ 2197679900 S2P_CSCWriteOK_Data2_28 "发送页数写入确认数据帧报文字节3";
CM_ SG_ 2197679900 S2P_CSCWriteOK_Data3_28 "发送页数写入确认数据帧报文字节4";
CM_ SG_ 2197679900 S2P_CSCWriteOK_Data4_28 "发送页数写入确认数据帧报文字节5";
CM_ SG_ 2197679900 S2P_CSCWriteOK_Data5_28 "发送页数写入确认数据帧报文字节6";
CM_ SG_ 2197679900 S2P_CSCWriteOK_Data6_28 "发送页数写入确认数据帧报文字节7";
CM_ SG_ 2197679900 S2P_CSCWriteOK_Data7_28 "发送页数写入确认数据帧报文字节8";
CM_ SG_ 2197679901 S2P_CSCWriteOK_Data0_29 "发送页数写入确认数据帧报文字节1";
CM_ SG_ 2197679901 S2P_CSCWriteOK_Data1_29 "发送页数写入确认数据帧报文字节2";
CM_ SG_ 2197679901 S2P_CSCWriteOK_Data2_29 "发送页数写入确认数据帧报文字节3";
CM_ SG_ 2197679901 S2P_CSCWriteOK_Data3_29 "发送页数写入确认数据帧报文字节4";
CM_ SG_ 2197679901 S2P_CSCWriteOK_Data4_29 "发送页数写入确认数据帧报文字节5";
CM_ SG_ 2197679901 S2P_CSCWriteOK_Data5_29 "发送页数写入确认数据帧报文字节6";
CM_ SG_ 2197679901 S2P_CSCWriteOK_Data6_29 "发送页数写入确认数据帧报文字节7";
CM_ SG_ 2197679901 S2P_CSCWriteOK_Data7_29 "发送页数写入确认数据帧报文字节8";
CM_ SG_ 2197679902 S2P_CSCWriteOK_Data0_30 "发送页数写入确认数据帧报文字节1";
CM_ SG_ 2197679902 S2P_CSCWriteOK_Data1_30 "发送页数写入确认数据帧报文字节2";
CM_ SG_ 2197679902 S2P_CSCWriteOK_Data2_30 "发送页数写入确认数据帧报文字节3";
CM_ SG_ 2197679902 S2P_CSCWriteOK_Data3_30 "发送页数写入确认数据帧报文字节4";
CM_ SG_ 2197679902 S2P_CSCWriteOK_Data4_30 "发送页数写入确认数据帧报文字节5";
CM_ SG_ 2197679902 S2P_CSCWriteOK_Data5_30 "发送页数写入确认数据帧报文字节6";
CM_ SG_ 2197679902 S2P_CSCWriteOK_Data6_30 "发送页数写入确认数据帧报文字节7";
CM_ SG_ 2197679902 S2P_CSCWriteOK_Data7_30 "发送页数写入确认数据帧报文字节8";
CM_ SG_ 2197679903 S2P_CSCWriteOK_Data0_31 "发送页数写入确认数据帧报文字节1";
CM_ SG_ 2197679903 S2P_CSCWriteOK_Data1_31 "发送页数写入确认数据帧报文字节2";
CM_ SG_ 2197679903 S2P_CSCWriteOK_Data2_31 "发送页数写入确认数据帧报文字节3";
CM_ SG_ 2197679903 S2P_CSCWriteOK_Data3_31 "发送页数写入确认数据帧报文字节4";
CM_ SG_ 2197679903 S2P_CSCWriteOK_Data4_31 "发送页数写入确认数据帧报文字节5";
CM_ SG_ 2197679903 S2P_CSCWriteOK_Data5_31 "发送页数写入确认数据帧报文字节6";
CM_ SG_ 2197679903 S2P_CSCWriteOK_Data6_31 "发送页数写入确认数据帧报文字节7";
CM_ SG_ 2197679903 S2P_CSCWriteOK_Data7_31 "发送页数写入确认数据帧报文字节8";
CM_ SG_ 2417815105 S2P_CSCPrgRslt_CSCPosition_01 "CSC更新程序成功标志";
CM_ SG_ 2417815106 S2P_CSCPrgRslt_CSCPosition_02 "CSC更新程序成功标志";
CM_ SG_ 2417815107 S2P_CSCPrgRslt_CSCPosition_03 "CSC更新程序成功标志";
CM_ SG_ 2417815108 S2P_CSCPrgRslt_CSCPosition_04 "CSC更新程序成功标志";
CM_ SG_ 2417815109 S2P_CSCPrgRslt_CSCPosition_05 "CSC更新程序成功标志";
CM_ SG_ 2417815110 S2P_CSCPrgRslt_CSCPosition_06 "CSC更新程序成功标志";
CM_ SG_ 2417815111 S2P_CSCPrgRslt_CSCPosition_07 "CSC更新程序成功标志";
CM_ SG_ 2417815112 S2P_CSCPrgRslt_CSCPosition_08 "CSC更新程序成功标志";
CM_ SG_ 2417815113 S2P_CSCPrgRslt_CSCPosition_09 "CSC更新程序成功标志";
CM_ SG_ 2417815114 S2P_CSCPrgRslt_CSCPosition_10 "CSC更新程序成功标志";
CM_ SG_ 2417815115 S2P_CSCPrgRslt_CSCPosition_11 "CSC更新程序成功标志";
CM_ SG_ 2417815116 S2P_CSCPrgRslt_CSCPosition_12 "CSC更新程序成功标志";
CM_ SG_ 2417815117 S2P_CSCPrgRslt_CSCPosition_13 "CSC更新程序成功标志";
CM_ SG_ 2417815118 S2P_CSCPrgRslt_CSCPosition_14 "CSC更新程序成功标志";
CM_ SG_ 2417815119 S2P_CSCPrgRslt_CSCPosition_15 "CSC更新程序成功标志";
CM_ SG_ 2417815120 S2P_CSCPrgRslt_CSCPosition_16 "CSC更新程序成功标志";
CM_ SG_ 2417815121 S2P_CSCPrgRslt_CSCPosition_17 "CSC更新程序成功标志";
CM_ SG_ 2417815122 S2P_CSCPrgRslt_CSCPosition_18 "CSC更新程序成功标志";
CM_ SG_ 2417815123 S2P_CSCPrgRslt_CSCPosition_19 "CSC更新程序成功标志";
CM_ SG_ 2417815124 S2P_CSCPrgRslt_CSCPosition_20 "CSC更新程序成功标志";
CM_ SG_ 2417815125 S2P_CSCPrgRslt_CSCPosition_21 "CSC更新程序成功标志";
CM_ SG_ 2417815126 S2P_CSCPrgRslt_CSCPosition_22 "CSC更新程序成功标志";
CM_ SG_ 2417815127 S2P_CSCPrgRslt_CSCPosition_23 "CSC更新程序成功标志";
CM_ SG_ 2417815128 S2P_CSCPrgRslt_CSCPosition_24 "CSC更新程序成功标志";
CM_ SG_ 2417815129 S2P_CSCPrgRslt_CSCPosition_25 "CSC更新程序成功标志";
CM_ SG_ 2417815130 S2P_CSCPrgRslt_CSCPosition_26 "CSC更新程序成功标志";
CM_ SG_ 2417815131 S2P_CSCPrgRslt_CSCPosition_27 "CSC更新程序成功标志";
CM_ SG_ 2417815132 S2P_CSCPrgRslt_CSCPosition_28 "CSC更新程序成功标志";
CM_ SG_ 2417815133 S2P_CSCPrgRslt_CSCPosition_29 "CSC更新程序成功标志";
CM_ SG_ 2417815134 S2P_CSCPrgRslt_CSCPosition_30 "CSC更新程序成功标志";
CM_ SG_ 2417815135 S2P_CSCPrgRslt_CSCPosition_31 "CSC更新程序成功标志";
CM_ SG_ 2417815136 S2P_CSCPrgRslt_CSCPosition_32 "CSC更新程序成功标志";
CM_ SG_ 2417815137 S2P_CSCPrgRslt_CSCPosition_33 "CSC更新程序成功标志";
CM_ SG_ 2417815138 S2P_CSCPrgRslt_CSCPosition_34 "CSC更新程序成功标志";
CM_ SG_ 2417815139 S2P_CSCPrgRslt_CSCPosition_35 "CSC更新程序成功标志";
CM_ SG_ 2417815140 S2P_CSCPrgRslt_CSCPosition_36 "CSC更新程序成功标志";
CM_ SG_ 2417815141 S2P_CSCPrgRslt_CSCPosition_37 "CSC更新程序成功标志";
CM_ SG_ 2417815142 S2P_CSCPrgRslt_CSCPosition_38 "CSC更新程序成功标志";
CM_ SG_ 2417815143 S2P_CSCPrgRslt_CSCPosition_39 "CSC更新程序成功标志";
CM_ SG_ 2417815144 S2P_CSCPrgRslt_CSCPosition_40 "CSC更新程序成功标志";
CM_ SG_ 2417815145 S2P_CSCPrgRslt_CSCPosition_41 "CSC更新程序成功标志";
CM_ SG_ 2417815146 S2P_CSCPrgRslt_CSCPosition_42 "CSC更新程序成功标志";
CM_ SG_ 2417815147 S2P_CSCPrgRslt_CSCPosition_43 "CSC更新程序成功标志";
CM_ SG_ 2417815148 S2P_CSCPrgRslt_CSCPosition_44 "CSC更新程序成功标志";
CM_ SG_ 2417815149 S2P_CSCPrgRslt_CSCPosition_45 "CSC更新程序成功标志";
CM_ SG_ 2417815150 S2P_CSCPrgRslt_CSCPosition_46 "CSC更新程序成功标志";
CM_ SG_ 2417815151 S2P_CSCPrgRslt_CSCPosition_47 "CSC更新程序成功标志";
CM_ SG_ 2417815152 S2P_CSCPrgRslt_CSCPosition_48 "CSC更新程序成功标志";
CM_ SG_ 2417815153 S2P_CSCPrgRslt_CSCPosition_49 "CSC更新程序成功标志";
CM_ SG_ 2417815154 S2P_CSCPrgRslt_CSCPosition_50 "CSC更新程序成功标志";
CM_ SG_ 2417815155 S2P_CSCPrgRslt_CSCPosition_51 "CSC更新程序成功标志";
CM_ SG_ 2417815156 S2P_CSCPrgRslt_CSCPosition_52 "CSC更新程序成功标志";
CM_ SG_ 2417815157 S2P_CSCPrgRslt_CSCPosition_53 "CSC更新程序成功标志";
CM_ SG_ 2417815158 S2P_CSCPrgRslt_CSCPosition_54 "CSC更新程序成功标志";
CM_ SG_ 2417815159 S2P_CSCPrgRslt_CSCPosition_55 "CSC更新程序成功标志";
CM_ SG_ 2417815160 S2P_CSCPrgRslt_CSCPosition_56 "CSC更新程序成功标志";
CM_ SG_ 2417815161 S2P_CSCPrgRslt_CSCPosition_57 "CSC更新程序成功标志";
CM_ SG_ 2417815162 S2P_CSCPrgRslt_CSCPosition_58 "CSC更新程序成功标志";
CM_ SG_ 2417815163 S2P_CSCPrgRslt_CSCPosition_59 "CSC更新程序成功标志";
CM_ SG_ 2417815164 S2P_CSCPrgRslt_CSCPosition_60 "CSC更新程序成功标志";
CM_ SG_ 2417815165 S2P_CSCPrgRslt_CSCPosition_61 "CSC更新程序成功标志";
CM_ SG_ 2417815166 S2P_CSCPrgRslt_CSCPosition_62 "CSC更新程序成功标志";
CM_ SG_ 2417815167 S2P_CSCPrgRslt_CSCPosition_63 "CSC更新程序成功标志";
CM_ SG_ 2148630417 HvPwrOnCmd_SBMU01_01 "高压控制指令";
CM_ SG_ 2148630417 HvPwrOnCmd_SBMU02_01 "高压控制指令";
CM_ SG_ 2148630417 HvPwrOnCmd_SBMU03_01 "高压控制指令";
CM_ SG_ 2148630417 HvPwrOnCmd_SBMU04_01 "高压控制指令";
CM_ SG_ 2148630417 HvPwrOnCmd_SBMU05_01 "高压控制指令";
CM_ SG_ 2148630417 HvPwrOnCmd_SBMU06_01 "高压控制指令";
CM_ SG_ 2148630417 HvPwrOnCmd_SBMU07_01 "高压控制指令";
CM_ SG_ 2148630417 HvPwrOnCmd_SBMU08_01 "高压控制指令";
CM_ SG_ 2148630417 HvPwrOnCmd_SBMU09_01 "高压控制指令";
CM_ SG_ 2148630417 HvPwrOnCmd_SBMU10_01 "高压控制指令";
CM_ SG_ 2148630417 HvPwrOnCmd_SBMU11_01 "高压控制指令";
CM_ SG_ 2148630417 HvPwrOnCmd_SBMU12_01 "高压控制指令";
CM_ SG_ 2148630417 HvPwrOnCmd_SBMU13_01 "高压控制指令";
CM_ SG_ 2148630417 HvPwrOnCmd_SBMU14_01 "高压控制指令";
CM_ SG_ 2148630417 HvPwrOnCmd_SBMU15_01 "高压控制指令";
CM_ SG_ 2148630417 HvPwrOnCmd_SBMU16_01 "高压控制指令";
CM_ SG_ 2148630417 HvPwrOnCmd_SBMU17_01 "高压控制指令";
CM_ SG_ 2148630417 HvPwrOnCmd_SBMU18_01 "高压控制指令";
CM_ SG_ 2148630417 HvPwrOnCmd_SBMU19_01 "高压控制指令";
CM_ SG_ 2148630417 HvPwrOnCmd_SBMU20_01 "高压控制指令";
CM_ SG_ 2148630417 HvPwrOnCmd_SBMU21_01 "高压控制指令";
CM_ SG_ 2148630417 HvPwrOnCmd_SBMU22_01 "高压控制指令";
CM_ SG_ 2148630417 HvPwrOnCmd_SBMU23_01 "高压控制指令";
CM_ SG_ 2148630417 HvPwrOnCmd_SBMU24_01 "高压控制指令";
CM_ SG_ 2148630417 HvPwrOnCmd_SBMU25_01 "高压控制指令";
CM_ SG_ 2148630417 HvPwrOnCmd_SBMU26_01 "高压控制指令";
CM_ SG_ 2148630417 HvPwrOnCmd_SBMU27_01 "高压控制指令";
CM_ SG_ 2148630417 HvPwrOnCmd_SBMU28_01 "高压控制指令";
CM_ SG_ 2148630417 HvPwrOnCmd_SBMU29_01 "高压控制指令";
CM_ SG_ 2148630417 HvPwrOnCmd_SBMU30_01 "高压控制指令";
CM_ SG_ 2148630417 HvPwrOnCmd_SBMU31_01 "高压控制指令";
CM_ SG_ 2148630417 HvPwrOnCmd_SBMU32_01 "高压控制指令";
CM_ SG_ 2148630418 HvPwrOnCmd_SBMU01_02 "高压控制指令";
CM_ SG_ 2148630418 HvPwrOnCmd_SBMU02_02 "高压控制指令";
CM_ SG_ 2148630418 HvPwrOnCmd_SBMU03_02 "高压控制指令";
CM_ SG_ 2148630418 HvPwrOnCmd_SBMU04_02 "高压控制指令";
CM_ SG_ 2148630418 HvPwrOnCmd_SBMU05_02 "高压控制指令";
CM_ SG_ 2148630418 HvPwrOnCmd_SBMU06_02 "高压控制指令";
CM_ SG_ 2148630418 HvPwrOnCmd_SBMU07_02 "高压控制指令";
CM_ SG_ 2148630418 HvPwrOnCmd_SBMU08_02 "高压控制指令";
CM_ SG_ 2148630418 HvPwrOnCmd_SBMU09_02 "高压控制指令";
CM_ SG_ 2148630418 HvPwrOnCmd_SBMU10_02 "高压控制指令";
CM_ SG_ 2148630418 HvPwrOnCmd_SBMU11_02 "高压控制指令";
CM_ SG_ 2148630418 HvPwrOnCmd_SBMU12_02 "高压控制指令";
CM_ SG_ 2148630418 HvPwrOnCmd_SBMU13_02 "高压控制指令";
CM_ SG_ 2148630418 HvPwrOnCmd_SBMU14_02 "高压控制指令";
CM_ SG_ 2148630418 HvPwrOnCmd_SBMU15_02 "高压控制指令";
CM_ SG_ 2148630418 HvPwrOnCmd_SBMU16_02 "高压控制指令";
CM_ SG_ 2148630418 HvPwrOnCmd_SBMU17_02 "高压控制指令";
CM_ SG_ 2148630418 HvPwrOnCmd_SBMU18_02 "高压控制指令";
CM_ SG_ 2148630418 HvPwrOnCmd_SBMU19_02 "高压控制指令";
CM_ SG_ 2148630418 HvPwrOnCmd_SBMU20_02 "高压控制指令";
CM_ SG_ 2148630418 HvPwrOnCmd_SBMU21_02 "高压控制指令";
CM_ SG_ 2148630418 HvPwrOnCmd_SBMU22_02 "高压控制指令";
CM_ SG_ 2148630418 HvPwrOnCmd_SBMU23_02 "高压控制指令";
CM_ SG_ 2148630418 HvPwrOnCmd_SBMU24_02 "高压控制指令";
CM_ SG_ 2148630418 HvPwrOnCmd_SBMU25_02 "高压控制指令";
CM_ SG_ 2148630418 HvPwrOnCmd_SBMU26_02 "高压控制指令";
CM_ SG_ 2148630418 HvPwrOnCmd_SBMU27_02 "高压控制指令";
CM_ SG_ 2148630418 HvPwrOnCmd_SBMU28_02 "高压控制指令";
CM_ SG_ 2148630418 HvPwrOnCmd_SBMU29_02 "高压控制指令";
CM_ SG_ 2148630418 HvPwrOnCmd_SBMU30_02 "高压控制指令";
CM_ SG_ 2148630418 HvPwrOnCmd_SBMU31_02 "高压控制指令";
CM_ SG_ 2148630418 HvPwrOnCmd_SBMU32_02 "高压控制指令";
CM_ SG_ 2148630419 HvPwrOnCmd_SBMU01_03 "高压控制指令";
CM_ SG_ 2148630419 HvPwrOnCmd_SBMU02_03 "高压控制指令";
CM_ SG_ 2148630419 HvPwrOnCmd_SBMU03_03 "高压控制指令";
CM_ SG_ 2148630419 HvPwrOnCmd_SBMU04_03 "高压控制指令";
CM_ SG_ 2148630419 HvPwrOnCmd_SBMU05_03 "高压控制指令";
CM_ SG_ 2148630419 HvPwrOnCmd_SBMU06_03 "高压控制指令";
CM_ SG_ 2148630419 HvPwrOnCmd_SBMU07_03 "高压控制指令";
CM_ SG_ 2148630419 HvPwrOnCmd_SBMU08_03 "高压控制指令";
CM_ SG_ 2148630419 HvPwrOnCmd_SBMU09_03 "高压控制指令";
CM_ SG_ 2148630419 HvPwrOnCmd_SBMU10_03 "高压控制指令";
CM_ SG_ 2148630419 HvPwrOnCmd_SBMU11_03 "高压控制指令";
CM_ SG_ 2148630419 HvPwrOnCmd_SBMU12_03 "高压控制指令";
CM_ SG_ 2148630419 HvPwrOnCmd_SBMU13_03 "高压控制指令";
CM_ SG_ 2148630419 HvPwrOnCmd_SBMU14_03 "高压控制指令";
CM_ SG_ 2148630419 HvPwrOnCmd_SBMU15_03 "高压控制指令";
CM_ SG_ 2148630419 HvPwrOnCmd_SBMU16_03 "高压控制指令";
CM_ SG_ 2148630419 HvPwrOnCmd_SBMU17_03 "高压控制指令";
CM_ SG_ 2148630419 HvPwrOnCmd_SBMU18_03 "高压控制指令";
CM_ SG_ 2148630419 HvPwrOnCmd_SBMU19_03 "高压控制指令";
CM_ SG_ 2148630419 HvPwrOnCmd_SBMU20_03 "高压控制指令";
CM_ SG_ 2148630419 HvPwrOnCmd_SBMU21_03 "高压控制指令";
CM_ SG_ 2148630419 HvPwrOnCmd_SBMU22_03 "高压控制指令";
CM_ SG_ 2148630419 HvPwrOnCmd_SBMU23_03 "高压控制指令";
CM_ SG_ 2148630419 HvPwrOnCmd_SBMU24_03 "高压控制指令";
CM_ SG_ 2148630419 HvPwrOnCmd_SBMU25_03 "高压控制指令";
CM_ SG_ 2148630419 HvPwrOnCmd_SBMU26_03 "高压控制指令";
CM_ SG_ 2148630419 HvPwrOnCmd_SBMU27_03 "高压控制指令";
CM_ SG_ 2148630419 HvPwrOnCmd_SBMU28_03 "高压控制指令";
CM_ SG_ 2148630419 HvPwrOnCmd_SBMU29_03 "高压控制指令";
CM_ SG_ 2148630419 HvPwrOnCmd_SBMU30_03 "高压控制指令";
CM_ SG_ 2148630419 HvPwrOnCmd_SBMU31_03 "高压控制指令";
CM_ SG_ 2148630419 HvPwrOnCmd_SBMU32_03 "高压控制指令";
CM_ SG_ 2148630420 HvPwrOnCmd_SBMU01_04 "高压控制指令";
CM_ SG_ 2148630420 HvPwrOnCmd_SBMU02_04 "高压控制指令";
CM_ SG_ 2148630420 HvPwrOnCmd_SBMU03_04 "高压控制指令";
CM_ SG_ 2148630420 HvPwrOnCmd_SBMU04_04 "高压控制指令";
CM_ SG_ 2148630420 HvPwrOnCmd_SBMU05_04 "高压控制指令";
CM_ SG_ 2148630420 HvPwrOnCmd_SBMU06_04 "高压控制指令";
CM_ SG_ 2148630420 HvPwrOnCmd_SBMU07_04 "高压控制指令";
CM_ SG_ 2148630420 HvPwrOnCmd_SBMU08_04 "高压控制指令";
CM_ SG_ 2148630420 HvPwrOnCmd_SBMU09_04 "高压控制指令";
CM_ SG_ 2148630420 HvPwrOnCmd_SBMU10_04 "高压控制指令";
CM_ SG_ 2148630420 HvPwrOnCmd_SBMU11_04 "高压控制指令";
CM_ SG_ 2148630420 HvPwrOnCmd_SBMU12_04 "高压控制指令";
CM_ SG_ 2148630420 HvPwrOnCmd_SBMU13_04 "高压控制指令";
CM_ SG_ 2148630420 HvPwrOnCmd_SBMU14_04 "高压控制指令";
CM_ SG_ 2148630420 HvPwrOnCmd_SBMU15_04 "高压控制指令";
CM_ SG_ 2148630420 HvPwrOnCmd_SBMU16_04 "高压控制指令";
CM_ SG_ 2148630420 HvPwrOnCmd_SBMU17_04 "高压控制指令";
CM_ SG_ 2148630420 HvPwrOnCmd_SBMU18_04 "高压控制指令";
CM_ SG_ 2148630420 HvPwrOnCmd_SBMU19_04 "高压控制指令";
CM_ SG_ 2148630420 HvPwrOnCmd_SBMU20_04 "高压控制指令";
CM_ SG_ 2148630420 HvPwrOnCmd_SBMU21_04 "高压控制指令";
CM_ SG_ 2148630420 HvPwrOnCmd_SBMU22_04 "高压控制指令";
CM_ SG_ 2148630420 HvPwrOnCmd_SBMU23_04 "高压控制指令";
CM_ SG_ 2148630420 HvPwrOnCmd_SBMU24_04 "高压控制指令";
CM_ SG_ 2148630420 HvPwrOnCmd_SBMU25_04 "高压控制指令";
CM_ SG_ 2148630420 HvPwrOnCmd_SBMU26_04 "高压控制指令";
CM_ SG_ 2148630420 HvPwrOnCmd_SBMU27_04 "高压控制指令";
CM_ SG_ 2148630420 HvPwrOnCmd_SBMU28_04 "高压控制指令";
CM_ SG_ 2148630420 HvPwrOnCmd_SBMU29_04 "高压控制指令";
CM_ SG_ 2148630420 HvPwrOnCmd_SBMU30_04 "高压控制指令";
CM_ SG_ 2148630420 HvPwrOnCmd_SBMU31_04 "高压控制指令";
CM_ SG_ 2148630420 HvPwrOnCmd_SBMU32_04 "高压控制指令";
CM_ SG_ 2148630421 HvPwrOnCmd_SBMU01_05 "高压控制指令";
CM_ SG_ 2148630421 HvPwrOnCmd_SBMU02_05 "高压控制指令";
CM_ SG_ 2148630421 HvPwrOnCmd_SBMU03_05 "高压控制指令";
CM_ SG_ 2148630421 HvPwrOnCmd_SBMU04_05 "高压控制指令";
CM_ SG_ 2148630421 HvPwrOnCmd_SBMU05_05 "高压控制指令";
CM_ SG_ 2148630421 HvPwrOnCmd_SBMU06_05 "高压控制指令";
CM_ SG_ 2148630421 HvPwrOnCmd_SBMU07_05 "高压控制指令";
CM_ SG_ 2148630421 HvPwrOnCmd_SBMU08_05 "高压控制指令";
CM_ SG_ 2148630421 HvPwrOnCmd_SBMU09_05 "高压控制指令";
CM_ SG_ 2148630421 HvPwrOnCmd_SBMU10_05 "高压控制指令";
CM_ SG_ 2148630421 HvPwrOnCmd_SBMU11_05 "高压控制指令";
CM_ SG_ 2148630421 HvPwrOnCmd_SBMU12_05 "高压控制指令";
CM_ SG_ 2148630421 HvPwrOnCmd_SBMU13_05 "高压控制指令";
CM_ SG_ 2148630421 HvPwrOnCmd_SBMU14_05 "高压控制指令";
CM_ SG_ 2148630421 HvPwrOnCmd_SBMU15_05 "高压控制指令";
CM_ SG_ 2148630421 HvPwrOnCmd_SBMU16_05 "高压控制指令";
CM_ SG_ 2148630421 HvPwrOnCmd_SBMU17_05 "高压控制指令";
CM_ SG_ 2148630421 HvPwrOnCmd_SBMU18_05 "高压控制指令";
CM_ SG_ 2148630421 HvPwrOnCmd_SBMU19_05 "高压控制指令";
CM_ SG_ 2148630421 HvPwrOnCmd_SBMU20_05 "高压控制指令";
CM_ SG_ 2148630421 HvPwrOnCmd_SBMU21_05 "高压控制指令";
CM_ SG_ 2148630421 HvPwrOnCmd_SBMU22_05 "高压控制指令";
CM_ SG_ 2148630421 HvPwrOnCmd_SBMU23_05 "高压控制指令";
CM_ SG_ 2148630421 HvPwrOnCmd_SBMU24_05 "高压控制指令";
CM_ SG_ 2148630421 HvPwrOnCmd_SBMU25_05 "高压控制指令";
CM_ SG_ 2148630421 HvPwrOnCmd_SBMU26_05 "高压控制指令";
CM_ SG_ 2148630421 HvPwrOnCmd_SBMU27_05 "高压控制指令";
CM_ SG_ 2148630421 HvPwrOnCmd_SBMU28_05 "高压控制指令";
CM_ SG_ 2148630421 HvPwrOnCmd_SBMU29_05 "高压控制指令";
CM_ SG_ 2148630421 HvPwrOnCmd_SBMU30_05 "高压控制指令";
CM_ SG_ 2148630421 HvPwrOnCmd_SBMU31_05 "高压控制指令";
CM_ SG_ 2148630421 HvPwrOnCmd_SBMU32_05 "高压控制指令";
CM_ SG_ 2148630422 HvPwrOnCmd_SBMU01_06 "高压控制指令";
CM_ SG_ 2148630422 HvPwrOnCmd_SBMU02_06 "高压控制指令";
CM_ SG_ 2148630422 HvPwrOnCmd_SBMU03_06 "高压控制指令";
CM_ SG_ 2148630422 HvPwrOnCmd_SBMU04_06 "高压控制指令";
CM_ SG_ 2148630422 HvPwrOnCmd_SBMU05_06 "高压控制指令";
CM_ SG_ 2148630422 HvPwrOnCmd_SBMU06_06 "高压控制指令";
CM_ SG_ 2148630422 HvPwrOnCmd_SBMU07_06 "高压控制指令";
CM_ SG_ 2148630422 HvPwrOnCmd_SBMU08_06 "高压控制指令";
CM_ SG_ 2148630422 HvPwrOnCmd_SBMU09_06 "高压控制指令";
CM_ SG_ 2148630422 HvPwrOnCmd_SBMU10_06 "高压控制指令";
CM_ SG_ 2148630422 HvPwrOnCmd_SBMU11_06 "高压控制指令";
CM_ SG_ 2148630422 HvPwrOnCmd_SBMU12_06 "高压控制指令";
CM_ SG_ 2148630422 HvPwrOnCmd_SBMU13_06 "高压控制指令";
CM_ SG_ 2148630422 HvPwrOnCmd_SBMU14_06 "高压控制指令";
CM_ SG_ 2148630422 HvPwrOnCmd_SBMU15_06 "高压控制指令";
CM_ SG_ 2148630422 HvPwrOnCmd_SBMU16_06 "高压控制指令";
CM_ SG_ 2148630422 HvPwrOnCmd_SBMU17_06 "高压控制指令";
CM_ SG_ 2148630422 HvPwrOnCmd_SBMU18_06 "高压控制指令";
CM_ SG_ 2148630422 HvPwrOnCmd_SBMU19_06 "高压控制指令";
CM_ SG_ 2148630422 HvPwrOnCmd_SBMU20_06 "高压控制指令";
CM_ SG_ 2148630422 HvPwrOnCmd_SBMU21_06 "高压控制指令";
CM_ SG_ 2148630422 HvPwrOnCmd_SBMU22_06 "高压控制指令";
CM_ SG_ 2148630422 HvPwrOnCmd_SBMU23_06 "高压控制指令";
CM_ SG_ 2148630422 HvPwrOnCmd_SBMU24_06 "高压控制指令";
CM_ SG_ 2148630422 HvPwrOnCmd_SBMU25_06 "高压控制指令";
CM_ SG_ 2148630422 HvPwrOnCmd_SBMU26_06 "高压控制指令";
CM_ SG_ 2148630422 HvPwrOnCmd_SBMU27_06 "高压控制指令";
CM_ SG_ 2148630422 HvPwrOnCmd_SBMU28_06 "高压控制指令";
CM_ SG_ 2148630422 HvPwrOnCmd_SBMU29_06 "高压控制指令";
CM_ SG_ 2148630422 HvPwrOnCmd_SBMU30_06 "高压控制指令";
CM_ SG_ 2148630422 HvPwrOnCmd_SBMU31_06 "高压控制指令";
CM_ SG_ 2148630422 HvPwrOnCmd_SBMU32_06 "高压控制指令";
CM_ SG_ 2148630423 HvPwrOnCmd_SBMU01_07 "高压控制指令";
CM_ SG_ 2148630423 HvPwrOnCmd_SBMU02_07 "高压控制指令";
CM_ SG_ 2148630423 HvPwrOnCmd_SBMU03_07 "高压控制指令";
CM_ SG_ 2148630423 HvPwrOnCmd_SBMU04_07 "高压控制指令";
CM_ SG_ 2148630423 HvPwrOnCmd_SBMU05_07 "高压控制指令";
CM_ SG_ 2148630423 HvPwrOnCmd_SBMU06_07 "高压控制指令";
CM_ SG_ 2148630423 HvPwrOnCmd_SBMU07_07 "高压控制指令";
CM_ SG_ 2148630423 HvPwrOnCmd_SBMU08_07 "高压控制指令";
CM_ SG_ 2148630423 HvPwrOnCmd_SBMU09_07 "高压控制指令";
CM_ SG_ 2148630423 HvPwrOnCmd_SBMU10_07 "高压控制指令";
CM_ SG_ 2148630423 HvPwrOnCmd_SBMU11_07 "高压控制指令";
CM_ SG_ 2148630423 HvPwrOnCmd_SBMU12_07 "高压控制指令";
CM_ SG_ 2148630423 HvPwrOnCmd_SBMU13_07 "高压控制指令";
CM_ SG_ 2148630423 HvPwrOnCmd_SBMU14_07 "高压控制指令";
CM_ SG_ 2148630423 HvPwrOnCmd_SBMU15_07 "高压控制指令";
CM_ SG_ 2148630423 HvPwrOnCmd_SBMU16_07 "高压控制指令";
CM_ SG_ 2148630423 HvPwrOnCmd_SBMU17_07 "高压控制指令";
CM_ SG_ 2148630423 HvPwrOnCmd_SBMU18_07 "高压控制指令";
CM_ SG_ 2148630423 HvPwrOnCmd_SBMU19_07 "高压控制指令";
CM_ SG_ 2148630423 HvPwrOnCmd_SBMU20_07 "高压控制指令";
CM_ SG_ 2148630423 HvPwrOnCmd_SBMU21_07 "高压控制指令";
CM_ SG_ 2148630423 HvPwrOnCmd_SBMU22_07 "高压控制指令";
CM_ SG_ 2148630423 HvPwrOnCmd_SBMU23_07 "高压控制指令";
CM_ SG_ 2148630423 HvPwrOnCmd_SBMU24_07 "高压控制指令";
CM_ SG_ 2148630423 HvPwrOnCmd_SBMU25_07 "高压控制指令";
CM_ SG_ 2148630423 HvPwrOnCmd_SBMU26_07 "高压控制指令";
CM_ SG_ 2148630423 HvPwrOnCmd_SBMU27_07 "高压控制指令";
CM_ SG_ 2148630423 HvPwrOnCmd_SBMU28_07 "高压控制指令";
CM_ SG_ 2148630423 HvPwrOnCmd_SBMU29_07 "高压控制指令";
CM_ SG_ 2148630423 HvPwrOnCmd_SBMU30_07 "高压控制指令";
CM_ SG_ 2148630423 HvPwrOnCmd_SBMU31_07 "高压控制指令";
CM_ SG_ 2148630423 HvPwrOnCmd_SBMU32_07 "高压控制指令";
CM_ SG_ 2148630424 HvPwrOnCmd_SBMU01_08 "高压控制指令";
CM_ SG_ 2148630424 HvPwrOnCmd_SBMU02_08 "高压控制指令";
CM_ SG_ 2148630424 HvPwrOnCmd_SBMU03_08 "高压控制指令";
CM_ SG_ 2148630424 HvPwrOnCmd_SBMU04_08 "高压控制指令";
CM_ SG_ 2148630424 HvPwrOnCmd_SBMU05_08 "高压控制指令";
CM_ SG_ 2148630424 HvPwrOnCmd_SBMU06_08 "高压控制指令";
CM_ SG_ 2148630424 HvPwrOnCmd_SBMU07_08 "高压控制指令";
CM_ SG_ 2148630424 HvPwrOnCmd_SBMU08_08 "高压控制指令";
CM_ SG_ 2148630424 HvPwrOnCmd_SBMU09_08 "高压控制指令";
CM_ SG_ 2148630424 HvPwrOnCmd_SBMU10_08 "高压控制指令";
CM_ SG_ 2148630424 HvPwrOnCmd_SBMU11_08 "高压控制指令";
CM_ SG_ 2148630424 HvPwrOnCmd_SBMU12_08 "高压控制指令";
CM_ SG_ 2148630424 HvPwrOnCmd_SBMU13_08 "高压控制指令";
CM_ SG_ 2148630424 HvPwrOnCmd_SBMU14_08 "高压控制指令";
CM_ SG_ 2148630424 HvPwrOnCmd_SBMU15_08 "高压控制指令";
CM_ SG_ 2148630424 HvPwrOnCmd_SBMU16_08 "高压控制指令";
CM_ SG_ 2148630424 HvPwrOnCmd_SBMU17_08 "高压控制指令";
CM_ SG_ 2148630424 HvPwrOnCmd_SBMU18_08 "高压控制指令";
CM_ SG_ 2148630424 HvPwrOnCmd_SBMU19_08 "高压控制指令";
CM_ SG_ 2148630424 HvPwrOnCmd_SBMU20_08 "高压控制指令";
CM_ SG_ 2148630424 HvPwrOnCmd_SBMU21_08 "高压控制指令";
CM_ SG_ 2148630424 HvPwrOnCmd_SBMU22_08 "高压控制指令";
CM_ SG_ 2148630424 HvPwrOnCmd_SBMU23_08 "高压控制指令";
CM_ SG_ 2148630424 HvPwrOnCmd_SBMU24_08 "高压控制指令";
CM_ SG_ 2148630424 HvPwrOnCmd_SBMU25_08 "高压控制指令";
CM_ SG_ 2148630424 HvPwrOnCmd_SBMU26_08 "高压控制指令";
CM_ SG_ 2148630424 HvPwrOnCmd_SBMU27_08 "高压控制指令";
CM_ SG_ 2148630424 HvPwrOnCmd_SBMU28_08 "高压控制指令";
CM_ SG_ 2148630424 HvPwrOnCmd_SBMU29_08 "高压控制指令";
CM_ SG_ 2148630424 HvPwrOnCmd_SBMU30_08 "高压控制指令";
CM_ SG_ 2148630424 HvPwrOnCmd_SBMU31_08 "高压控制指令";
CM_ SG_ 2148630424 HvPwrOnCmd_SBMU32_08 "高压控制指令";
CM_ SG_ 2148630425 HvPwrOnCmd_SBMU01_09 "高压控制指令";
CM_ SG_ 2148630425 HvPwrOnCmd_SBMU02_09 "高压控制指令";
CM_ SG_ 2148630425 HvPwrOnCmd_SBMU03_09 "高压控制指令";
CM_ SG_ 2148630425 HvPwrOnCmd_SBMU04_09 "高压控制指令";
CM_ SG_ 2148630425 HvPwrOnCmd_SBMU05_09 "高压控制指令";
CM_ SG_ 2148630425 HvPwrOnCmd_SBMU06_09 "高压控制指令";
CM_ SG_ 2148630425 HvPwrOnCmd_SBMU07_09 "高压控制指令";
CM_ SG_ 2148630425 HvPwrOnCmd_SBMU08_09 "高压控制指令";
CM_ SG_ 2148630425 HvPwrOnCmd_SBMU09_09 "高压控制指令";
CM_ SG_ 2148630425 HvPwrOnCmd_SBMU10_09 "高压控制指令";
CM_ SG_ 2148630425 HvPwrOnCmd_SBMU11_09 "高压控制指令";
CM_ SG_ 2148630425 HvPwrOnCmd_SBMU12_09 "高压控制指令";
CM_ SG_ 2148630425 HvPwrOnCmd_SBMU13_09 "高压控制指令";
CM_ SG_ 2148630425 HvPwrOnCmd_SBMU14_09 "高压控制指令";
CM_ SG_ 2148630425 HvPwrOnCmd_SBMU15_09 "高压控制指令";
CM_ SG_ 2148630425 HvPwrOnCmd_SBMU16_09 "高压控制指令";
CM_ SG_ 2148630425 HvPwrOnCmd_SBMU17_09 "高压控制指令";
CM_ SG_ 2148630425 HvPwrOnCmd_SBMU18_09 "高压控制指令";
CM_ SG_ 2148630425 HvPwrOnCmd_SBMU19_09 "高压控制指令";
CM_ SG_ 2148630425 HvPwrOnCmd_SBMU20_09 "高压控制指令";
CM_ SG_ 2148630425 HvPwrOnCmd_SBMU21_09 "高压控制指令";
CM_ SG_ 2148630425 HvPwrOnCmd_SBMU22_09 "高压控制指令";
CM_ SG_ 2148630425 HvPwrOnCmd_SBMU23_09 "高压控制指令";
CM_ SG_ 2148630425 HvPwrOnCmd_SBMU24_09 "高压控制指令";
CM_ SG_ 2148630425 HvPwrOnCmd_SBMU25_09 "高压控制指令";
CM_ SG_ 2148630425 HvPwrOnCmd_SBMU26_09 "高压控制指令";
CM_ SG_ 2148630425 HvPwrOnCmd_SBMU27_09 "高压控制指令";
CM_ SG_ 2148630425 HvPwrOnCmd_SBMU28_09 "高压控制指令";
CM_ SG_ 2148630425 HvPwrOnCmd_SBMU29_09 "高压控制指令";
CM_ SG_ 2148630425 HvPwrOnCmd_SBMU30_09 "高压控制指令";
CM_ SG_ 2148630425 HvPwrOnCmd_SBMU31_09 "高压控制指令";
CM_ SG_ 2148630425 HvPwrOnCmd_SBMU32_09 "高压控制指令";
CM_ SG_ 2148630426 HvPwrOnCmd_SBMU01_10 "高压控制指令";
CM_ SG_ 2148630426 HvPwrOnCmd_SBMU02_10 "高压控制指令";
CM_ SG_ 2148630426 HvPwrOnCmd_SBMU03_10 "高压控制指令";
CM_ SG_ 2148630426 HvPwrOnCmd_SBMU04_10 "高压控制指令";
CM_ SG_ 2148630426 HvPwrOnCmd_SBMU05_10 "高压控制指令";
CM_ SG_ 2148630426 HvPwrOnCmd_SBMU06_10 "高压控制指令";
CM_ SG_ 2148630426 HvPwrOnCmd_SBMU07_10 "高压控制指令";
CM_ SG_ 2148630426 HvPwrOnCmd_SBMU08_10 "高压控制指令";
CM_ SG_ 2148630426 HvPwrOnCmd_SBMU09_10 "高压控制指令";
CM_ SG_ 2148630426 HvPwrOnCmd_SBMU10_10 "高压控制指令";
CM_ SG_ 2148630426 HvPwrOnCmd_SBMU11_10 "高压控制指令";
CM_ SG_ 2148630426 HvPwrOnCmd_SBMU12_10 "高压控制指令";
CM_ SG_ 2148630426 HvPwrOnCmd_SBMU13_10 "高压控制指令";
CM_ SG_ 2148630426 HvPwrOnCmd_SBMU14_10 "高压控制指令";
CM_ SG_ 2148630426 HvPwrOnCmd_SBMU15_10 "高压控制指令";
CM_ SG_ 2148630426 HvPwrOnCmd_SBMU16_10 "高压控制指令";
CM_ SG_ 2148630426 HvPwrOnCmd_SBMU17_10 "高压控制指令";
CM_ SG_ 2148630426 HvPwrOnCmd_SBMU18_10 "高压控制指令";
CM_ SG_ 2148630426 HvPwrOnCmd_SBMU19_10 "高压控制指令";
CM_ SG_ 2148630426 HvPwrOnCmd_SBMU20_10 "高压控制指令";
CM_ SG_ 2148630426 HvPwrOnCmd_SBMU21_10 "高压控制指令";
CM_ SG_ 2148630426 HvPwrOnCmd_SBMU22_10 "高压控制指令";
CM_ SG_ 2148630426 HvPwrOnCmd_SBMU23_10 "高压控制指令";
CM_ SG_ 2148630426 HvPwrOnCmd_SBMU24_10 "高压控制指令";
CM_ SG_ 2148630426 HvPwrOnCmd_SBMU25_10 "高压控制指令";
CM_ SG_ 2148630426 HvPwrOnCmd_SBMU26_10 "高压控制指令";
CM_ SG_ 2148630426 HvPwrOnCmd_SBMU27_10 "高压控制指令";
CM_ SG_ 2148630426 HvPwrOnCmd_SBMU28_10 "高压控制指令";
CM_ SG_ 2148630426 HvPwrOnCmd_SBMU29_10 "高压控制指令";
CM_ SG_ 2148630426 HvPwrOnCmd_SBMU30_10 "高压控制指令";
CM_ SG_ 2148630426 HvPwrOnCmd_SBMU31_10 "高压控制指令";
CM_ SG_ 2148630426 HvPwrOnCmd_SBMU32_10 "高压控制指令";
CM_ SG_ 2148630427 HvPwrOnCmd_SBMU01_11 "高压控制指令";
CM_ SG_ 2148630427 HvPwrOnCmd_SBMU02_11 "高压控制指令";
CM_ SG_ 2148630427 HvPwrOnCmd_SBMU03_11 "高压控制指令";
CM_ SG_ 2148630427 HvPwrOnCmd_SBMU04_11 "高压控制指令";
CM_ SG_ 2148630427 HvPwrOnCmd_SBMU05_11 "高压控制指令";
CM_ SG_ 2148630427 HvPwrOnCmd_SBMU06_11 "高压控制指令";
CM_ SG_ 2148630427 HvPwrOnCmd_SBMU07_11 "高压控制指令";
CM_ SG_ 2148630427 HvPwrOnCmd_SBMU08_11 "高压控制指令";
CM_ SG_ 2148630427 HvPwrOnCmd_SBMU09_11 "高压控制指令";
CM_ SG_ 2148630427 HvPwrOnCmd_SBMU10_11 "高压控制指令";
CM_ SG_ 2148630427 HvPwrOnCmd_SBMU11_11 "高压控制指令";
CM_ SG_ 2148630427 HvPwrOnCmd_SBMU12_11 "高压控制指令";
CM_ SG_ 2148630427 HvPwrOnCmd_SBMU13_11 "高压控制指令";
CM_ SG_ 2148630427 HvPwrOnCmd_SBMU14_11 "高压控制指令";
CM_ SG_ 2148630427 HvPwrOnCmd_SBMU15_11 "高压控制指令";
CM_ SG_ 2148630427 HvPwrOnCmd_SBMU16_11 "高压控制指令";
CM_ SG_ 2148630427 HvPwrOnCmd_SBMU17_11 "高压控制指令";
CM_ SG_ 2148630427 HvPwrOnCmd_SBMU18_11 "高压控制指令";
CM_ SG_ 2148630427 HvPwrOnCmd_SBMU19_11 "高压控制指令";
CM_ SG_ 2148630427 HvPwrOnCmd_SBMU20_11 "高压控制指令";
CM_ SG_ 2148630427 HvPwrOnCmd_SBMU21_11 "高压控制指令";
CM_ SG_ 2148630427 HvPwrOnCmd_SBMU22_11 "高压控制指令";
CM_ SG_ 2148630427 HvPwrOnCmd_SBMU23_11 "高压控制指令";
CM_ SG_ 2148630427 HvPwrOnCmd_SBMU24_11 "高压控制指令";
CM_ SG_ 2148630427 HvPwrOnCmd_SBMU25_11 "高压控制指令";
CM_ SG_ 2148630427 HvPwrOnCmd_SBMU26_11 "高压控制指令";
CM_ SG_ 2148630427 HvPwrOnCmd_SBMU27_11 "高压控制指令";
CM_ SG_ 2148630427 HvPwrOnCmd_SBMU28_11 "高压控制指令";
CM_ SG_ 2148630427 HvPwrOnCmd_SBMU29_11 "高压控制指令";
CM_ SG_ 2148630427 HvPwrOnCmd_SBMU30_11 "高压控制指令";
CM_ SG_ 2148630427 HvPwrOnCmd_SBMU31_11 "高压控制指令";
CM_ SG_ 2148630427 HvPwrOnCmd_SBMU32_11 "高压控制指令";
CM_ SG_ 2148630428 HvPwrOnCmd_SBMU01_12 "高压控制指令";
CM_ SG_ 2148630428 HvPwrOnCmd_SBMU02_12 "高压控制指令";
CM_ SG_ 2148630428 HvPwrOnCmd_SBMU03_12 "高压控制指令";
CM_ SG_ 2148630428 HvPwrOnCmd_SBMU04_12 "高压控制指令";
CM_ SG_ 2148630428 HvPwrOnCmd_SBMU05_12 "高压控制指令";
CM_ SG_ 2148630428 HvPwrOnCmd_SBMU06_12 "高压控制指令";
CM_ SG_ 2148630428 HvPwrOnCmd_SBMU07_12 "高压控制指令";
CM_ SG_ 2148630428 HvPwrOnCmd_SBMU08_12 "高压控制指令";
CM_ SG_ 2148630428 HvPwrOnCmd_SBMU09_12 "高压控制指令";
CM_ SG_ 2148630428 HvPwrOnCmd_SBMU10_12 "高压控制指令";
CM_ SG_ 2148630428 HvPwrOnCmd_SBMU11_12 "高压控制指令";
CM_ SG_ 2148630428 HvPwrOnCmd_SBMU12_12 "高压控制指令";
CM_ SG_ 2148630428 HvPwrOnCmd_SBMU13_12 "高压控制指令";
CM_ SG_ 2148630428 HvPwrOnCmd_SBMU14_12 "高压控制指令";
CM_ SG_ 2148630428 HvPwrOnCmd_SBMU15_12 "高压控制指令";
CM_ SG_ 2148630428 HvPwrOnCmd_SBMU16_12 "高压控制指令";
CM_ SG_ 2148630428 HvPwrOnCmd_SBMU17_12 "高压控制指令";
CM_ SG_ 2148630428 HvPwrOnCmd_SBMU18_12 "高压控制指令";
CM_ SG_ 2148630428 HvPwrOnCmd_SBMU19_12 "高压控制指令";
CM_ SG_ 2148630428 HvPwrOnCmd_SBMU20_12 "高压控制指令";
CM_ SG_ 2148630428 HvPwrOnCmd_SBMU21_12 "高压控制指令";
CM_ SG_ 2148630428 HvPwrOnCmd_SBMU22_12 "高压控制指令";
CM_ SG_ 2148630428 HvPwrOnCmd_SBMU23_12 "高压控制指令";
CM_ SG_ 2148630428 HvPwrOnCmd_SBMU24_12 "高压控制指令";
CM_ SG_ 2148630428 HvPwrOnCmd_SBMU25_12 "高压控制指令";
CM_ SG_ 2148630428 HvPwrOnCmd_SBMU26_12 "高压控制指令";
CM_ SG_ 2148630428 HvPwrOnCmd_SBMU27_12 "高压控制指令";
CM_ SG_ 2148630428 HvPwrOnCmd_SBMU28_12 "高压控制指令";
CM_ SG_ 2148630428 HvPwrOnCmd_SBMU29_12 "高压控制指令";
CM_ SG_ 2148630428 HvPwrOnCmd_SBMU30_12 "高压控制指令";
CM_ SG_ 2148630428 HvPwrOnCmd_SBMU31_12 "高压控制指令";
CM_ SG_ 2148630428 HvPwrOnCmd_SBMU32_12 "高压控制指令";
CM_ SG_ 2148630429 HvPwrOnCmd_SBMU01_13 "高压控制指令";
CM_ SG_ 2148630429 HvPwrOnCmd_SBMU02_13 "高压控制指令";
CM_ SG_ 2148630429 HvPwrOnCmd_SBMU03_13 "高压控制指令";
CM_ SG_ 2148630429 HvPwrOnCmd_SBMU04_13 "高压控制指令";
CM_ SG_ 2148630429 HvPwrOnCmd_SBMU05_13 "高压控制指令";
CM_ SG_ 2148630429 HvPwrOnCmd_SBMU06_13 "高压控制指令";
CM_ SG_ 2148630429 HvPwrOnCmd_SBMU07_13 "高压控制指令";
CM_ SG_ 2148630429 HvPwrOnCmd_SBMU08_13 "高压控制指令";
CM_ SG_ 2148630429 HvPwrOnCmd_SBMU09_13 "高压控制指令";
CM_ SG_ 2148630429 HvPwrOnCmd_SBMU10_13 "高压控制指令";
CM_ SG_ 2148630429 HvPwrOnCmd_SBMU11_13 "高压控制指令";
CM_ SG_ 2148630429 HvPwrOnCmd_SBMU12_13 "高压控制指令";
CM_ SG_ 2148630429 HvPwrOnCmd_SBMU13_13 "高压控制指令";
CM_ SG_ 2148630429 HvPwrOnCmd_SBMU14_13 "高压控制指令";
CM_ SG_ 2148630429 HvPwrOnCmd_SBMU15_13 "高压控制指令";
CM_ SG_ 2148630429 HvPwrOnCmd_SBMU16_13 "高压控制指令";
CM_ SG_ 2148630429 HvPwrOnCmd_SBMU17_13 "高压控制指令";
CM_ SG_ 2148630429 HvPwrOnCmd_SBMU18_13 "高压控制指令";
CM_ SG_ 2148630429 HvPwrOnCmd_SBMU19_13 "高压控制指令";
CM_ SG_ 2148630429 HvPwrOnCmd_SBMU20_13 "高压控制指令";
CM_ SG_ 2148630429 HvPwrOnCmd_SBMU21_13 "高压控制指令";
CM_ SG_ 2148630429 HvPwrOnCmd_SBMU22_13 "高压控制指令";
CM_ SG_ 2148630429 HvPwrOnCmd_SBMU23_13 "高压控制指令";
CM_ SG_ 2148630429 HvPwrOnCmd_SBMU24_13 "高压控制指令";
CM_ SG_ 2148630429 HvPwrOnCmd_SBMU25_13 "高压控制指令";
CM_ SG_ 2148630429 HvPwrOnCmd_SBMU26_13 "高压控制指令";
CM_ SG_ 2148630429 HvPwrOnCmd_SBMU27_13 "高压控制指令";
CM_ SG_ 2148630429 HvPwrOnCmd_SBMU28_13 "高压控制指令";
CM_ SG_ 2148630429 HvPwrOnCmd_SBMU29_13 "高压控制指令";
CM_ SG_ 2148630429 HvPwrOnCmd_SBMU30_13 "高压控制指令";
CM_ SG_ 2148630429 HvPwrOnCmd_SBMU31_13 "高压控制指令";
CM_ SG_ 2148630429 HvPwrOnCmd_SBMU32_13 "高压控制指令";
CM_ SG_ 2148630430 HvPwrOnCmd_SBMU01_14 "高压控制指令";
CM_ SG_ 2148630430 HvPwrOnCmd_SBMU02_14 "高压控制指令";
CM_ SG_ 2148630430 HvPwrOnCmd_SBMU03_14 "高压控制指令";
CM_ SG_ 2148630430 HvPwrOnCmd_SBMU04_14 "高压控制指令";
CM_ SG_ 2148630430 HvPwrOnCmd_SBMU05_14 "高压控制指令";
CM_ SG_ 2148630430 HvPwrOnCmd_SBMU06_14 "高压控制指令";
CM_ SG_ 2148630430 HvPwrOnCmd_SBMU07_14 "高压控制指令";
CM_ SG_ 2148630430 HvPwrOnCmd_SBMU08_14 "高压控制指令";
CM_ SG_ 2148630430 HvPwrOnCmd_SBMU09_14 "高压控制指令";
CM_ SG_ 2148630430 HvPwrOnCmd_SBMU10_14 "高压控制指令";
CM_ SG_ 2148630430 HvPwrOnCmd_SBMU11_14 "高压控制指令";
CM_ SG_ 2148630430 HvPwrOnCmd_SBMU12_14 "高压控制指令";
CM_ SG_ 2148630430 HvPwrOnCmd_SBMU13_14 "高压控制指令";
CM_ SG_ 2148630430 HvPwrOnCmd_SBMU14_14 "高压控制指令";
CM_ SG_ 2148630430 HvPwrOnCmd_SBMU15_14 "高压控制指令";
CM_ SG_ 2148630430 HvPwrOnCmd_SBMU16_14 "高压控制指令";
CM_ SG_ 2148630430 HvPwrOnCmd_SBMU17_14 "高压控制指令";
CM_ SG_ 2148630430 HvPwrOnCmd_SBMU18_14 "高压控制指令";
CM_ SG_ 2148630430 HvPwrOnCmd_SBMU19_14 "高压控制指令";
CM_ SG_ 2148630430 HvPwrOnCmd_SBMU20_14 "高压控制指令";
CM_ SG_ 2148630430 HvPwrOnCmd_SBMU21_14 "高压控制指令";
CM_ SG_ 2148630430 HvPwrOnCmd_SBMU22_14 "高压控制指令";
CM_ SG_ 2148630430 HvPwrOnCmd_SBMU23_14 "高压控制指令";
CM_ SG_ 2148630430 HvPwrOnCmd_SBMU24_14 "高压控制指令";
CM_ SG_ 2148630430 HvPwrOnCmd_SBMU25_14 "高压控制指令";
CM_ SG_ 2148630430 HvPwrOnCmd_SBMU26_14 "高压控制指令";
CM_ SG_ 2148630430 HvPwrOnCmd_SBMU27_14 "高压控制指令";
CM_ SG_ 2148630430 HvPwrOnCmd_SBMU28_14 "高压控制指令";
CM_ SG_ 2148630430 HvPwrOnCmd_SBMU29_14 "高压控制指令";
CM_ SG_ 2148630430 HvPwrOnCmd_SBMU30_14 "高压控制指令";
CM_ SG_ 2148630430 HvPwrOnCmd_SBMU31_14 "高压控制指令";
CM_ SG_ 2148630430 HvPwrOnCmd_SBMU32_14 "高压控制指令";
CM_ SG_ 2148630431 HvPwrOnCmd_SBMU01_15 "高压控制指令";
CM_ SG_ 2148630431 HvPwrOnCmd_SBMU02_15 "高压控制指令";
CM_ SG_ 2148630431 HvPwrOnCmd_SBMU03_15 "高压控制指令";
CM_ SG_ 2148630431 HvPwrOnCmd_SBMU04_15 "高压控制指令";
CM_ SG_ 2148630431 HvPwrOnCmd_SBMU05_15 "高压控制指令";
CM_ SG_ 2148630431 HvPwrOnCmd_SBMU06_15 "高压控制指令";
CM_ SG_ 2148630431 HvPwrOnCmd_SBMU07_15 "高压控制指令";
CM_ SG_ 2148630431 HvPwrOnCmd_SBMU08_15 "高压控制指令";
CM_ SG_ 2148630431 HvPwrOnCmd_SBMU09_15 "高压控制指令";
CM_ SG_ 2148630431 HvPwrOnCmd_SBMU10_15 "高压控制指令";
CM_ SG_ 2148630431 HvPwrOnCmd_SBMU11_15 "高压控制指令";
CM_ SG_ 2148630431 HvPwrOnCmd_SBMU12_15 "高压控制指令";
CM_ SG_ 2148630431 HvPwrOnCmd_SBMU13_15 "高压控制指令";
CM_ SG_ 2148630431 HvPwrOnCmd_SBMU14_15 "高压控制指令";
CM_ SG_ 2148630431 HvPwrOnCmd_SBMU15_15 "高压控制指令";
CM_ SG_ 2148630431 HvPwrOnCmd_SBMU16_15 "高压控制指令";
CM_ SG_ 2148630431 HvPwrOnCmd_SBMU17_15 "高压控制指令";
CM_ SG_ 2148630431 HvPwrOnCmd_SBMU18_15 "高压控制指令";
CM_ SG_ 2148630431 HvPwrOnCmd_SBMU19_15 "高压控制指令";
CM_ SG_ 2148630431 HvPwrOnCmd_SBMU20_15 "高压控制指令";
CM_ SG_ 2148630431 HvPwrOnCmd_SBMU21_15 "高压控制指令";
CM_ SG_ 2148630431 HvPwrOnCmd_SBMU22_15 "高压控制指令";
CM_ SG_ 2148630431 HvPwrOnCmd_SBMU23_15 "高压控制指令";
CM_ SG_ 2148630431 HvPwrOnCmd_SBMU24_15 "高压控制指令";
CM_ SG_ 2148630431 HvPwrOnCmd_SBMU25_15 "高压控制指令";
CM_ SG_ 2148630431 HvPwrOnCmd_SBMU26_15 "高压控制指令";
CM_ SG_ 2148630431 HvPwrOnCmd_SBMU27_15 "高压控制指令";
CM_ SG_ 2148630431 HvPwrOnCmd_SBMU28_15 "高压控制指令";
CM_ SG_ 2148630431 HvPwrOnCmd_SBMU29_15 "高压控制指令";
CM_ SG_ 2148630431 HvPwrOnCmd_SBMU30_15 "高压控制指令";
CM_ SG_ 2148630431 HvPwrOnCmd_SBMU31_15 "高压控制指令";
CM_ SG_ 2148630431 HvPwrOnCmd_SBMU32_15 "高压控制指令";
CM_ SG_ 2148630432 HvPwrOnCmd_SBMU01_16 "高压控制指令";
CM_ SG_ 2148630432 HvPwrOnCmd_SBMU02_16 "高压控制指令";
CM_ SG_ 2148630432 HvPwrOnCmd_SBMU03_16 "高压控制指令";
CM_ SG_ 2148630432 HvPwrOnCmd_SBMU04_16 "高压控制指令";
CM_ SG_ 2148630432 HvPwrOnCmd_SBMU05_16 "高压控制指令";
CM_ SG_ 2148630432 HvPwrOnCmd_SBMU06_16 "高压控制指令";
CM_ SG_ 2148630432 HvPwrOnCmd_SBMU07_16 "高压控制指令";
CM_ SG_ 2148630432 HvPwrOnCmd_SBMU08_16 "高压控制指令";
CM_ SG_ 2148630432 HvPwrOnCmd_SBMU09_16 "高压控制指令";
CM_ SG_ 2148630432 HvPwrOnCmd_SBMU10_16 "高压控制指令";
CM_ SG_ 2148630432 HvPwrOnCmd_SBMU11_16 "高压控制指令";
CM_ SG_ 2148630432 HvPwrOnCmd_SBMU12_16 "高压控制指令";
CM_ SG_ 2148630432 HvPwrOnCmd_SBMU13_16 "高压控制指令";
CM_ SG_ 2148630432 HvPwrOnCmd_SBMU14_16 "高压控制指令";
CM_ SG_ 2148630432 HvPwrOnCmd_SBMU15_16 "高压控制指令";
CM_ SG_ 2148630432 HvPwrOnCmd_SBMU16_16 "高压控制指令";
CM_ SG_ 2148630432 HvPwrOnCmd_SBMU17_16 "高压控制指令";
CM_ SG_ 2148630432 HvPwrOnCmd_SBMU18_16 "高压控制指令";
CM_ SG_ 2148630432 HvPwrOnCmd_SBMU19_16 "高压控制指令";
CM_ SG_ 2148630432 HvPwrOnCmd_SBMU20_16 "高压控制指令";
CM_ SG_ 2148630432 HvPwrOnCmd_SBMU21_16 "高压控制指令";
CM_ SG_ 2148630432 HvPwrOnCmd_SBMU22_16 "高压控制指令";
CM_ SG_ 2148630432 HvPwrOnCmd_SBMU23_16 "高压控制指令";
CM_ SG_ 2148630432 HvPwrOnCmd_SBMU24_16 "高压控制指令";
CM_ SG_ 2148630432 HvPwrOnCmd_SBMU25_16 "高压控制指令";
CM_ SG_ 2148630432 HvPwrOnCmd_SBMU26_16 "高压控制指令";
CM_ SG_ 2148630432 HvPwrOnCmd_SBMU27_16 "高压控制指令";
CM_ SG_ 2148630432 HvPwrOnCmd_SBMU28_16 "高压控制指令";
CM_ SG_ 2148630432 HvPwrOnCmd_SBMU29_16 "高压控制指令";
CM_ SG_ 2148630432 HvPwrOnCmd_SBMU30_16 "高压控制指令";
CM_ SG_ 2148630432 HvPwrOnCmd_SBMU31_16 "高压控制指令";
CM_ SG_ 2148630432 HvPwrOnCmd_SBMU32_16 "高压控制指令";
VAL_ 2417815105 S2P_CSCPrgRslt_CSCPosition_01 0 "All CSC Success" 1 "CSC1 Fail" 2 "CSC2 Fail" 4 "CSC3 Fail" 8 "CSC4 Fail" 16 "CSC5 Fail" 32 "CSC6 Fail" 64 "CSC7 Fail" ;
VAL_ 2417815106 S2P_CSCPrgRslt_CSCPosition_02 0 "All CSC Success" 1 "CSC1 Fail" 2 "CSC2 Fail" 4 "CSC3 Fail" 8 "CSC4 Fail" 16 "CSC5 Fail" 32 "CSC6 Fail" 64 "CSC7 Fail" ;
VAL_ 2417815107 S2P_CSCPrgRslt_CSCPosition_03 0 "All CSC Success" 1 "CSC1 Fail" 2 "CSC2 Fail" 4 "CSC3 Fail" 8 "CSC4 Fail" 16 "CSC5 Fail" 32 "CSC6 Fail" 64 "CSC7 Fail" ;
VAL_ 2417815108 S2P_CSCPrgRslt_CSCPosition_04 0 "All CSC Success" 1 "CSC1 Fail" 2 "CSC2 Fail" 4 "CSC3 Fail" 8 "CSC4 Fail" 16 "CSC5 Fail" 32 "CSC6 Fail" 64 "CSC7 Fail" ;
VAL_ 2417815109 S2P_CSCPrgRslt_CSCPosition_05 0 "All CSC Success" 1 "CSC1 Fail" 2 "CSC2 Fail" 4 "CSC3 Fail" 8 "CSC4 Fail" 16 "CSC5 Fail" 32 "CSC6 Fail" 64 "CSC7 Fail" ;
VAL_ 2417815110 S2P_CSCPrgRslt_CSCPosition_06 0 "All CSC Success" 1 "CSC1 Fail" 2 "CSC2 Fail" 4 "CSC3 Fail" 8 "CSC4 Fail" 16 "CSC5 Fail" 32 "CSC6 Fail" 64 "CSC7 Fail" ;
VAL_ 2417815111 S2P_CSCPrgRslt_CSCPosition_07 0 "All CSC Success" 1 "CSC1 Fail" 2 "CSC2 Fail" 4 "CSC3 Fail" 8 "CSC4 Fail" 16 "CSC5 Fail" 32 "CSC6 Fail" 64 "CSC7 Fail" ;
VAL_ 2417815112 S2P_CSCPrgRslt_CSCPosition_08 0 "All CSC Success" 1 "CSC1 Fail" 2 "CSC2 Fail" 4 "CSC3 Fail" 8 "CSC4 Fail" 16 "CSC5 Fail" 32 "CSC6 Fail" 64 "CSC7 Fail" ;
VAL_ 2417815113 S2P_CSCPrgRslt_CSCPosition_09 0 "All CSC Success" 1 "CSC1 Fail" 2 "CSC2 Fail" 4 "CSC3 Fail" 8 "CSC4 Fail" 16 "CSC5 Fail" 32 "CSC6 Fail" 64 "CSC7 Fail" ;
VAL_ 2417815114 S2P_CSCPrgRslt_CSCPosition_10 0 "All CSC Success" 1 "CSC1 Fail" 2 "CSC2 Fail" 4 "CSC3 Fail" 8 "CSC4 Fail" 16 "CSC5 Fail" 32 "CSC6 Fail" 64 "CSC7 Fail" ;
VAL_ 2417815115 S2P_CSCPrgRslt_CSCPosition_11 0 "All CSC Success" 1 "CSC1 Fail" 2 "CSC2 Fail" 4 "CSC3 Fail" 8 "CSC4 Fail" 16 "CSC5 Fail" 32 "CSC6 Fail" 64 "CSC7 Fail" ;
VAL_ 2417815116 S2P_CSCPrgRslt_CSCPosition_12 0 "All CSC Success" 1 "CSC1 Fail" 2 "CSC2 Fail" 4 "CSC3 Fail" 8 "CSC4 Fail" 16 "CSC5 Fail" 32 "CSC6 Fail" 64 "CSC7 Fail" ;
VAL_ 2417815117 S2P_CSCPrgRslt_CSCPosition_13 0 "All CSC Success" 1 "CSC1 Fail" 2 "CSC2 Fail" 4 "CSC3 Fail" 8 "CSC4 Fail" 16 "CSC5 Fail" 32 "CSC6 Fail" 64 "CSC7 Fail" ;
VAL_ 2417815118 S2P_CSCPrgRslt_CSCPosition_14 0 "All CSC Success" 1 "CSC1 Fail" 2 "CSC2 Fail" 4 "CSC3 Fail" 8 "CSC4 Fail" 16 "CSC5 Fail" 32 "CSC6 Fail" 64 "CSC7 Fail" ;
VAL_ 2417815119 S2P_CSCPrgRslt_CSCPosition_15 0 "All CSC Success" 1 "CSC1 Fail" 2 "CSC2 Fail" 4 "CSC3 Fail" 8 "CSC4 Fail" 16 "CSC5 Fail" 32 "CSC6 Fail" 64 "CSC7 Fail" ;
VAL_ 2417815120 S2P_CSCPrgRslt_CSCPosition_16 0 "All CSC Success" 1 "CSC1 Fail" 2 "CSC2 Fail" 4 "CSC3 Fail" 8 "CSC4 Fail" 16 "CSC5 Fail" 32 "CSC6 Fail" 64 "CSC7 Fail" ;
VAL_ 2417815121 S2P_CSCPrgRslt_CSCPosition_17 0 "All CSC Success" 1 "CSC1 Fail" 2 "CSC2 Fail" 4 "CSC3 Fail" 8 "CSC4 Fail" 16 "CSC5 Fail" 32 "CSC6 Fail" 64 "CSC7 Fail" ;
VAL_ 2417815122 S2P_CSCPrgRslt_CSCPosition_18 0 "All CSC Success" 1 "CSC1 Fail" 2 "CSC2 Fail" 4 "CSC3 Fail" 8 "CSC4 Fail" 16 "CSC5 Fail" 32 "CSC6 Fail" 64 "CSC7 Fail" ;
VAL_ 2417815123 S2P_CSCPrgRslt_CSCPosition_19 0 "All CSC Success" 1 "CSC1 Fail" 2 "CSC2 Fail" 4 "CSC3 Fail" 8 "CSC4 Fail" 16 "CSC5 Fail" 32 "CSC6 Fail" 64 "CSC7 Fail" ;
VAL_ 2417815124 S2P_CSCPrgRslt_CSCPosition_20 0 "All CSC Success" 1 "CSC1 Fail" 2 "CSC2 Fail" 4 "CSC3 Fail" 8 "CSC4 Fail" 16 "CSC5 Fail" 32 "CSC6 Fail" 64 "CSC7 Fail" ;
VAL_ 2417815125 S2P_CSCPrgRslt_CSCPosition_21 0 "All CSC Success" 1 "CSC1 Fail" 2 "CSC2 Fail" 4 "CSC3 Fail" 8 "CSC4 Fail" 16 "CSC5 Fail" 32 "CSC6 Fail" 64 "CSC7 Fail" ;
VAL_ 2417815126 S2P_CSCPrgRslt_CSCPosition_22 0 "All CSC Success" 1 "CSC1 Fail" 2 "CSC2 Fail" 4 "CSC3 Fail" 8 "CSC4 Fail" 16 "CSC5 Fail" 32 "CSC6 Fail" 64 "CSC7 Fail" ;
VAL_ 2417815127 S2P_CSCPrgRslt_CSCPosition_23 0 "All CSC Success" 1 "CSC1 Fail" 2 "CSC2 Fail" 4 "CSC3 Fail" 8 "CSC4 Fail" 16 "CSC5 Fail" 32 "CSC6 Fail" 64 "CSC7 Fail" ;
VAL_ 2417815128 S2P_CSCPrgRslt_CSCPosition_24 0 "All CSC Success" 1 "CSC1 Fail" 2 "CSC2 Fail" 4 "CSC3 Fail" 8 "CSC4 Fail" 16 "CSC5 Fail" 32 "CSC6 Fail" 64 "CSC7 Fail" ;
VAL_ 2417815129 S2P_CSCPrgRslt_CSCPosition_25 0 "All CSC Success" 1 "CSC1 Fail" 2 "CSC2 Fail" 4 "CSC3 Fail" 8 "CSC4 Fail" 16 "CSC5 Fail" 32 "CSC6 Fail" 64 "CSC7 Fail" ;
VAL_ 2417815130 S2P_CSCPrgRslt_CSCPosition_26 0 "All CSC Success" 1 "CSC1 Fail" 2 "CSC2 Fail" 4 "CSC3 Fail" 8 "CSC4 Fail" 16 "CSC5 Fail" 32 "CSC6 Fail" 64 "CSC7 Fail" ;
VAL_ 2417815131 S2P_CSCPrgRslt_CSCPosition_27 0 "All CSC Success" 1 "CSC1 Fail" 2 "CSC2 Fail" 4 "CSC3 Fail" 8 "CSC4 Fail" 16 "CSC5 Fail" 32 "CSC6 Fail" 64 "CSC7 Fail" ;
VAL_ 2417815132 S2P_CSCPrgRslt_CSCPosition_28 0 "All CSC Success" 1 "CSC1 Fail" 2 "CSC2 Fail" 4 "CSC3 Fail" 8 "CSC4 Fail" 16 "CSC5 Fail" 32 "CSC6 Fail" 64 "CSC7 Fail" ;
VAL_ 2417815133 S2P_CSCPrgRslt_CSCPosition_29 0 "All CSC Success" 1 "CSC1 Fail" 2 "CSC2 Fail" 4 "CSC3 Fail" 8 "CSC4 Fail" 16 "CSC5 Fail" 32 "CSC6 Fail" 64 "CSC7 Fail" ;
VAL_ 2417815134 S2P_CSCPrgRslt_CSCPosition_30 0 "All CSC Success" 1 "CSC1 Fail" 2 "CSC2 Fail" 4 "CSC3 Fail" 8 "CSC4 Fail" 16 "CSC5 Fail" 32 "CSC6 Fail" 64 "CSC7 Fail" ;
VAL_ 2417815135 S2P_CSCPrgRslt_CSCPosition_31 0 "All CSC Success" 1 "CSC1 Fail" 2 "CSC2 Fail" 4 "CSC3 Fail" 8 "CSC4 Fail" 16 "CSC5 Fail" 32 "CSC6 Fail" 64 "CSC7 Fail" ;
VAL_ 2417815136 S2P_CSCPrgRslt_CSCPosition_32 0 "All CSC Success" 1 "CSC1 Fail" 2 "CSC2 Fail" 4 "CSC3 Fail" 8 "CSC4 Fail" 16 "CSC5 Fail" 32 "CSC6 Fail" 64 "CSC7 Fail" ;
VAL_ 2417815137 S2P_CSCPrgRslt_CSCPosition_33 0 "All CSC Success" 1 "CSC1 Fail" 2 "CSC2 Fail" 4 "CSC3 Fail" 8 "CSC4 Fail" 16 "CSC5 Fail" 32 "CSC6 Fail" 64 "CSC7 Fail" ;
VAL_ 2417815138 S2P_CSCPrgRslt_CSCPosition_34 0 "All CSC Success" 1 "CSC1 Fail" 2 "CSC2 Fail" 4 "CSC3 Fail" 8 "CSC4 Fail" 16 "CSC5 Fail" 32 "CSC6 Fail" 64 "CSC7 Fail" ;
VAL_ 2417815139 S2P_CSCPrgRslt_CSCPosition_35 0 "All CSC Success" 1 "CSC1 Fail" 2 "CSC2 Fail" 4 "CSC3 Fail" 8 "CSC4 Fail" 16 "CSC5 Fail" 32 "CSC6 Fail" 64 "CSC7 Fail" ;
VAL_ 2417815140 S2P_CSCPrgRslt_CSCPosition_36 0 "All CSC Success" 1 "CSC1 Fail" 2 "CSC2 Fail" 4 "CSC3 Fail" 8 "CSC4 Fail" 16 "CSC5 Fail" 32 "CSC6 Fail" 64 "CSC7 Fail" ;
VAL_ 2417815141 S2P_CSCPrgRslt_CSCPosition_37 0 "All CSC Success" 1 "CSC1 Fail" 2 "CSC2 Fail" 4 "CSC3 Fail" 8 "CSC4 Fail" 16 "CSC5 Fail" 32 "CSC6 Fail" 64 "CSC7 Fail" ;
VAL_ 2417815142 S2P_CSCPrgRslt_CSCPosition_38 0 "All CSC Success" 1 "CSC1 Fail" 2 "CSC2 Fail" 4 "CSC3 Fail" 8 "CSC4 Fail" 16 "CSC5 Fail" 32 "CSC6 Fail" 64 "CSC7 Fail" ;
VAL_ 2417815143 S2P_CSCPrgRslt_CSCPosition_39 0 "All CSC Success" 1 "CSC1 Fail" 2 "CSC2 Fail" 4 "CSC3 Fail" 8 "CSC4 Fail" 16 "CSC5 Fail" 32 "CSC6 Fail" 64 "CSC7 Fail" ;
VAL_ 2417815144 S2P_CSCPrgRslt_CSCPosition_40 0 "All CSC Success" 1 "CSC1 Fail" 2 "CSC2 Fail" 4 "CSC3 Fail" 8 "CSC4 Fail" 16 "CSC5 Fail" 32 "CSC6 Fail" 64 "CSC7 Fail" ;
VAL_ 2417815145 S2P_CSCPrgRslt_CSCPosition_41 0 "All CSC Success" 1 "CSC1 Fail" 2 "CSC2 Fail" 4 "CSC3 Fail" 8 "CSC4 Fail" 16 "CSC5 Fail" 32 "CSC6 Fail" 64 "CSC7 Fail" ;
VAL_ 2417815146 S2P_CSCPrgRslt_CSCPosition_42 0 "All CSC Success" 1 "CSC1 Fail" 2 "CSC2 Fail" 4 "CSC3 Fail" 8 "CSC4 Fail" 16 "CSC5 Fail" 32 "CSC6 Fail" 64 "CSC7 Fail" ;
VAL_ 2417815147 S2P_CSCPrgRslt_CSCPosition_43 0 "All CSC Success" 1 "CSC1 Fail" 2 "CSC2 Fail" 4 "CSC3 Fail" 8 "CSC4 Fail" 16 "CSC5 Fail" 32 "CSC6 Fail" 64 "CSC7 Fail" ;
VAL_ 2417815148 S2P_CSCPrgRslt_CSCPosition_44 0 "All CSC Success" 1 "CSC1 Fail" 2 "CSC2 Fail" 4 "CSC3 Fail" 8 "CSC4 Fail" 16 "CSC5 Fail" 32 "CSC6 Fail" 64 "CSC7 Fail" ;
VAL_ 2417815149 S2P_CSCPrgRslt_CSCPosition_45 0 "All CSC Success" 1 "CSC1 Fail" 2 "CSC2 Fail" 4 "CSC3 Fail" 8 "CSC4 Fail" 16 "CSC5 Fail" 32 "CSC6 Fail" 64 "CSC7 Fail" ;
VAL_ 2417815150 S2P_CSCPrgRslt_CSCPosition_46 0 "All CSC Success" 1 "CSC1 Fail" 2 "CSC2 Fail" 4 "CSC3 Fail" 8 "CSC4 Fail" 16 "CSC5 Fail" 32 "CSC6 Fail" 64 "CSC7 Fail" ;
VAL_ 2417815151 S2P_CSCPrgRslt_CSCPosition_47 0 "All CSC Success" 1 "CSC1 Fail" 2 "CSC2 Fail" 4 "CSC3 Fail" 8 "CSC4 Fail" 16 "CSC5 Fail" 32 "CSC6 Fail" 64 "CSC7 Fail" ;
VAL_ 2417815152 S2P_CSCPrgRslt_CSCPosition_48 0 "All CSC Success" 1 "CSC1 Fail" 2 "CSC2 Fail" 4 "CSC3 Fail" 8 "CSC4 Fail" 16 "CSC5 Fail" 32 "CSC6 Fail" 64 "CSC7 Fail" ;
VAL_ 2417815153 S2P_CSCPrgRslt_CSCPosition_49 0 "All CSC Success" 1 "CSC1 Fail" 2 "CSC2 Fail" 4 "CSC3 Fail" 8 "CSC4 Fail" 16 "CSC5 Fail" 32 "CSC6 Fail" 64 "CSC7 Fail" ;
VAL_ 2417815154 S2P_CSCPrgRslt_CSCPosition_50 0 "All CSC Success" 1 "CSC1 Fail" 2 "CSC2 Fail" 4 "CSC3 Fail" 8 "CSC4 Fail" 16 "CSC5 Fail" 32 "CSC6 Fail" 64 "CSC7 Fail" ;
VAL_ 2417815155 S2P_CSCPrgRslt_CSCPosition_51 0 "All CSC Success" 1 "CSC1 Fail" 2 "CSC2 Fail" 4 "CSC3 Fail" 8 "CSC4 Fail" 16 "CSC5 Fail" 32 "CSC6 Fail" 64 "CSC7 Fail" ;
VAL_ 2417815156 S2P_CSCPrgRslt_CSCPosition_52 0 "All CSC Success" 1 "CSC1 Fail" 2 "CSC2 Fail" 4 "CSC3 Fail" 8 "CSC4 Fail" 16 "CSC5 Fail" 32 "CSC6 Fail" 64 "CSC7 Fail" ;
VAL_ 2417815157 S2P_CSCPrgRslt_CSCPosition_53 0 "All CSC Success" 1 "CSC1 Fail" 2 "CSC2 Fail" 4 "CSC3 Fail" 8 "CSC4 Fail" 16 "CSC5 Fail" 32 "CSC6 Fail" 64 "CSC7 Fail" ;
VAL_ 2417815158 S2P_CSCPrgRslt_CSCPosition_54 0 "All CSC Success" 1 "CSC1 Fail" 2 "CSC2 Fail" 4 "CSC3 Fail" 8 "CSC4 Fail" 16 "CSC5 Fail" 32 "CSC6 Fail" 64 "CSC7 Fail" ;
VAL_ 2417815159 S2P_CSCPrgRslt_CSCPosition_55 0 "All CSC Success" 1 "CSC1 Fail" 2 "CSC2 Fail" 4 "CSC3 Fail" 8 "CSC4 Fail" 16 "CSC5 Fail" 32 "CSC6 Fail" 64 "CSC7 Fail" ;
VAL_ 2417815160 S2P_CSCPrgRslt_CSCPosition_56 0 "All CSC Success" 1 "CSC1 Fail" 2 "CSC2 Fail" 4 "CSC3 Fail" 8 "CSC4 Fail" 16 "CSC5 Fail" 32 "CSC6 Fail" 64 "CSC7 Fail" ;
VAL_ 2417815161 S2P_CSCPrgRslt_CSCPosition_57 0 "All CSC Success" 1 "CSC1 Fail" 2 "CSC2 Fail" 4 "CSC3 Fail" 8 "CSC4 Fail" 16 "CSC5 Fail" 32 "CSC6 Fail" 64 "CSC7 Fail" ;
VAL_ 2417815162 S2P_CSCPrgRslt_CSCPosition_58 0 "All CSC Success" 1 "CSC1 Fail" 2 "CSC2 Fail" 4 "CSC3 Fail" 8 "CSC4 Fail" 16 "CSC5 Fail" 32 "CSC6 Fail" 64 "CSC7 Fail" ;
VAL_ 2417815163 S2P_CSCPrgRslt_CSCPosition_59 0 "All CSC Success" 1 "CSC1 Fail" 2 "CSC2 Fail" 4 "CSC3 Fail" 8 "CSC4 Fail" 16 "CSC5 Fail" 32 "CSC6 Fail" 64 "CSC7 Fail" ;
VAL_ 2417815164 S2P_CSCPrgRslt_CSCPosition_60 0 "All CSC Success" 1 "CSC1 Fail" 2 "CSC2 Fail" 4 "CSC3 Fail" 8 "CSC4 Fail" 16 "CSC5 Fail" 32 "CSC6 Fail" 64 "CSC7 Fail" ;
VAL_ 2417815165 S2P_CSCPrgRslt_CSCPosition_61 0 "All CSC Success" 1 "CSC1 Fail" 2 "CSC2 Fail" 4 "CSC3 Fail" 8 "CSC4 Fail" 16 "CSC5 Fail" 32 "CSC6 Fail" 64 "CSC7 Fail" ;
VAL_ 2417815166 S2P_CSCPrgRslt_CSCPosition_62 0 "All CSC Success" 1 "CSC1 Fail" 2 "CSC2 Fail" 4 "CSC3 Fail" 8 "CSC4 Fail" 16 "CSC5 Fail" 32 "CSC6 Fail" 64 "CSC7 Fail" ;
VAL_ 2417815167 S2P_CSCPrgRslt_CSCPosition_63 0 "All CSC Success" 1 "CSC1 Fail" 2 "CSC2 Fail" 4 "CSC3 Fail" 8 "CSC4 Fail" 16 "CSC5 Fail" 32 "CSC6 Fail" 64 "CSC7 Fail" ;
VAL_ 2148630417 HvPwrOnCmd_SBMU01_01 0 "请求正常下高压" 1 "请求上高压" 2 "强制SBMU下高压" ;
VAL_ 2148630417 HvPwrOnCmd_SBMU02_01 0 "请求正常下高压" 1 "请求上高压" 2 "强制SBMU下高压" ;
VAL_ 2148630417 HvPwrOnCmd_SBMU03_01 0 "请求正常下高压" 1 "请求上高压" 2 "强制SBMU下高压" ;
VAL_ 2148630417 HvPwrOnCmd_SBMU04_01 0 "请求正常下高压" 1 "请求上高压" 2 "强制SBMU下高压" ;
VAL_ 2148630417 HvPwrOnCmd_SBMU05_01 0 "请求正常下高压" 1 "请求上高压" 2 "强制SBMU下高压" ;
VAL_ 2148630417 HvPwrOnCmd_SBMU06_01 0 "请求正常下高压" 1 "请求上高压" 2 "强制SBMU下高压" ;
VAL_ 2148630417 HvPwrOnCmd_SBMU07_01 0 "请求正常下高压" 1 "请求上高压" 2 "强制SBMU下高压" ;
VAL_ 2148630417 HvPwrOnCmd_SBMU08_01 0 "请求正常下高压" 1 "请求上高压" 2 "强制SBMU下高压" ;
VAL_ 2148630417 HvPwrOnCmd_SBMU09_01 0 "请求正常下高压" 1 "请求上高压" 2 "强制SBMU下高压" ;
VAL_ 2148630417 HvPwrOnCmd_SBMU10_01 0 "请求正常下高压" 1 "请求上高压" 2 "强制SBMU下高压" ;
VAL_ 2148630417 HvPwrOnCmd_SBMU11_01 0 "请求正常下高压" 1 "请求上高压" 2 "强制SBMU下高压" ;
VAL_ 2148630417 HvPwrOnCmd_SBMU12_01 0 "请求正常下高压" 1 "请求上高压" 2 "强制SBMU下高压" ;
VAL_ 2148630417 HvPwrOnCmd_SBMU13_01 0 "请求正常下高压" 1 "请求上高压" 2 "强制SBMU下高压" ;
VAL_ 2148630417 HvPwrOnCmd_SBMU14_01 0 "请求正常下高压" 1 "请求上高压" 2 "强制SBMU下高压" ;
VAL_ 2148630417 HvPwrOnCmd_SBMU15_01 0 "请求正常下高压" 1 "请求上高压" 2 "强制SBMU下高压" ;
VAL_ 2148630417 HvPwrOnCmd_SBMU16_01 0 "请求正常下高压" 1 "请求上高压" 2 "强制SBMU下高压" ;
VAL_ 2148630417 HvPwrOnCmd_SBMU17_01 0 "请求正常下高压" 1 "请求上高压" 2 "强制SBMU下高压" ;
VAL_ 2148630417 HvPwrOnCmd_SBMU18_01 0 "请求正常下高压" 1 "请求上高压" 2 "强制SBMU下高压" ;
VAL_ 2148630417 HvPwrOnCmd_SBMU19_01 0 "请求正常下高压" 1 "请求上高压" 2 "强制SBMU下高压" ;
VAL_ 2148630417 HvPwrOnCmd_SBMU20_01 0 "请求正常下高压" 1 "请求上高压" 2 "强制SBMU下高压" ;
VAL_ 2148630417 HvPwrOnCmd_SBMU21_01 0 "请求正常下高压" 1 "请求上高压" 2 "强制SBMU下高压" ;
VAL_ 2148630417 HvPwrOnCmd_SBMU22_01 0 "请求正常下高压" 1 "请求上高压" 2 "强制SBMU下高压" ;
VAL_ 2148630417 HvPwrOnCmd_SBMU23_01 0 "请求正常下高压" 1 "请求上高压" 2 "强制SBMU下高压" ;
VAL_ 2148630417 HvPwrOnCmd_SBMU24_01 0 "请求正常下高压" 1 "请求上高压" 2 "强制SBMU下高压" ;
VAL_ 2148630417 HvPwrOnCmd_SBMU25_01 0 "请求正常下高压" 1 "请求上高压" 2 "强制SBMU下高压" ;
VAL_ 2148630417 HvPwrOnCmd_SBMU26_01 0 "请求正常下高压" 1 "请求上高压" 2 "强制SBMU下高压" ;
VAL_ 2148630417 HvPwrOnCmd_SBMU27_01 0 "请求正常下高压" 1 "请求上高压" 2 "强制SBMU下高压" ;
VAL_ 2148630417 HvPwrOnCmd_SBMU28_01 0 "请求正常下高压" 1 "请求上高压" 2 "强制SBMU下高压" ;
VAL_ 2148630417 HvPwrOnCmd_SBMU29_01 0 "请求正常下高压" 1 "请求上高压" 2 "强制SBMU下高压" ;
VAL_ 2148630417 HvPwrOnCmd_SBMU30_01 0 "请求正常下高压" 1 "请求上高压" 2 "强制SBMU下高压" ;
VAL_ 2148630417 HvPwrOnCmd_SBMU31_01 0 "请求正常下高压" 1 "请求上高压" 2 "强制SBMU下高压" ;
VAL_ 2148630417 HvPwrOnCmd_SBMU32_01 0 "请求正常下高压" 1 "请求上高压" 2 "强制SBMU下高压" ;
VAL_ 2148630418 HvPwrOnCmd_SBMU01_02 0 "请求正常下高压" 1 "请求上高压" 2 "强制SBMU下高压" ;
VAL_ 2148630418 HvPwrOnCmd_SBMU02_02 0 "请求正常下高压" 1 "请求上高压" 2 "强制SBMU下高压" ;
VAL_ 2148630418 HvPwrOnCmd_SBMU03_02 0 "请求正常下高压" 1 "请求上高压" 2 "强制SBMU下高压" ;
VAL_ 2148630418 HvPwrOnCmd_SBMU04_02 0 "请求正常下高压" 1 "请求上高压" 2 "强制SBMU下高压" ;
VAL_ 2148630418 HvPwrOnCmd_SBMU05_02 0 "请求正常下高压" 1 "请求上高压" 2 "强制SBMU下高压" ;
VAL_ 2148630418 HvPwrOnCmd_SBMU06_02 0 "请求正常下高压" 1 "请求上高压" 2 "强制SBMU下高压" ;
VAL_ 2148630418 HvPwrOnCmd_SBMU07_02 0 "请求正常下高压" 1 "请求上高压" 2 "强制SBMU下高压" ;
VAL_ 2148630418 HvPwrOnCmd_SBMU08_02 0 "请求正常下高压" 1 "请求上高压" 2 "强制SBMU下高压" ;
VAL_ 2148630418 HvPwrOnCmd_SBMU09_02 0 "请求正常下高压" 1 "请求上高压" 2 "强制SBMU下高压" ;
VAL_ 2148630418 HvPwrOnCmd_SBMU10_02 0 "请求正常下高压" 1 "请求上高压" 2 "强制SBMU下高压" ;
VAL_ 2148630418 HvPwrOnCmd_SBMU11_02 0 "请求正常下高压" 1 "请求上高压" 2 "强制SBMU下高压" ;
VAL_ 2148630418 HvPwrOnCmd_SBMU12_02 0 "请求正常下高压" 1 "请求上高压" 2 "强制SBMU下高压" ;
VAL_ 2148630418 HvPwrOnCmd_SBMU13_02 0 "请求正常下高压" 1 "请求上高压" 2 "强制SBMU下高压" ;
VAL_ 2148630418 HvPwrOnCmd_SBMU14_02 0 "请求正常下高压" 1 "请求上高压" 2 "强制SBMU下高压" ;
VAL_ 2148630418 HvPwrOnCmd_SBMU15_02 0 "请求正常下高压" 1 "请求上高压" 2 "强制SBMU下高压" ;
VAL_ 2148630418 HvPwrOnCmd_SBMU16_02 0 "请求正常下高压" 1 "请求上高压" 2 "强制SBMU下高压" ;
VAL_ 2148630418 HvPwrOnCmd_SBMU17_02 0 "请求正常下高压" 1 "请求上高压" 2 "强制SBMU下高压" ;
VAL_ 2148630418 HvPwrOnCmd_SBMU18_02 0 "请求正常下高压" 1 "请求上高压" 2 "强制SBMU下高压" ;
VAL_ 2148630418 HvPwrOnCmd_SBMU19_02 0 "请求正常下高压" 1 "请求上高压" 2 "强制SBMU下高压" ;
VAL_ 2148630418 HvPwrOnCmd_SBMU20_02 0 "请求正常下高压" 1 "请求上高压" 2 "强制SBMU下高压" ;
VAL_ 2148630418 HvPwrOnCmd_SBMU21_02 0 "请求正常下高压" 1 "请求上高压" 2 "强制SBMU下高压" ;
VAL_ 2148630418 HvPwrOnCmd_SBMU22_02 0 "请求正常下高压" 1 "请求上高压" 2 "强制SBMU下高压" ;
VAL_ 2148630418 HvPwrOnCmd_SBMU23_02 0 "请求正常下高压" 1 "请求上高压" 2 "强制SBMU下高压" ;
VAL_ 2148630418 HvPwrOnCmd_SBMU24_02 0 "请求正常下高压" 1 "请求上高压" 2 "强制SBMU下高压" ;
VAL_ 2148630418 HvPwrOnCmd_SBMU25_02 0 "请求正常下高压" 1 "请求上高压" 2 "强制SBMU下高压" ;
VAL_ 2148630418 HvPwrOnCmd_SBMU26_02 0 "请求正常下高压" 1 "请求上高压" 2 "强制SBMU下高压" ;
VAL_ 2148630418 HvPwrOnCmd_SBMU27_02 0 "请求正常下高压" 1 "请求上高压" 2 "强制SBMU下高压" ;
VAL_ 2148630418 HvPwrOnCmd_SBMU28_02 0 "请求正常下高压" 1 "请求上高压" 2 "强制SBMU下高压" ;
VAL_ 2148630418 HvPwrOnCmd_SBMU29_02 0 "请求正常下高压" 1 "请求上高压" 2 "强制SBMU下高压" ;
VAL_ 2148630418 HvPwrOnCmd_SBMU30_02 0 "请求正常下高压" 1 "请求上高压" 2 "强制SBMU下高压" ;
VAL_ 2148630418 HvPwrOnCmd_SBMU31_02 0 "请求正常下高压" 1 "请求上高压" 2 "强制SBMU下高压" ;
VAL_ 2148630418 HvPwrOnCmd_SBMU32_02 0 "请求正常下高压" 1 "请求上高压" 2 "强制SBMU下高压" ;
VAL_ 2148630419 HvPwrOnCmd_SBMU01_03 0 "请求正常下高压" 1 "请求上高压" 2 "强制SBMU下高压" ;
VAL_ 2148630419 HvPwrOnCmd_SBMU02_03 0 "请求正常下高压" 1 "请求上高压" 2 "强制SBMU下高压" ;
VAL_ 2148630419 HvPwrOnCmd_SBMU03_03 0 "请求正常下高压" 1 "请求上高压" 2 "强制SBMU下高压" ;
VAL_ 2148630419 HvPwrOnCmd_SBMU04_03 0 "请求正常下高压" 1 "请求上高压" 2 "强制SBMU下高压" ;
VAL_ 2148630419 HvPwrOnCmd_SBMU05_03 0 "请求正常下高压" 1 "请求上高压" 2 "强制SBMU下高压" ;
VAL_ 2148630419 HvPwrOnCmd_SBMU06_03 0 "请求正常下高压" 1 "请求上高压" 2 "强制SBMU下高压" ;
VAL_ 2148630419 HvPwrOnCmd_SBMU07_03 0 "请求正常下高压" 1 "请求上高压" 2 "强制SBMU下高压" ;
VAL_ 2148630419 HvPwrOnCmd_SBMU08_03 0 "请求正常下高压" 1 "请求上高压" 2 "强制SBMU下高压" ;
VAL_ 2148630419 HvPwrOnCmd_SBMU09_03 0 "请求正常下高压" 1 "请求上高压" 2 "强制SBMU下高压" ;
VAL_ 2148630419 HvPwrOnCmd_SBMU10_03 0 "请求正常下高压" 1 "请求上高压" 2 "强制SBMU下高压" ;
VAL_ 2148630419 HvPwrOnCmd_SBMU11_03 0 "请求正常下高压" 1 "请求上高压" 2 "强制SBMU下高压" ;
VAL_ 2148630419 HvPwrOnCmd_SBMU12_03 0 "请求正常下高压" 1 "请求上高压" 2 "强制SBMU下高压" ;
VAL_ 2148630419 HvPwrOnCmd_SBMU13_03 0 "请求正常下高压" 1 "请求上高压" 2 "强制SBMU下高压" ;
VAL_ 2148630419 HvPwrOnCmd_SBMU14_03 0 "请求正常下高压" 1 "请求上高压" 2 "强制SBMU下高压" ;
VAL_ 2148630419 HvPwrOnCmd_SBMU15_03 0 "请求正常下高压" 1 "请求上高压" 2 "强制SBMU下高压" ;
VAL_ 2148630419 HvPwrOnCmd_SBMU16_03 0 "请求正常下高压" 1 "请求上高压" 2 "强制SBMU下高压" ;
VAL_ 2148630419 HvPwrOnCmd_SBMU17_03 0 "请求正常下高压" 1 "请求上高压" 2 "强制SBMU下高压" ;
VAL_ 2148630419 HvPwrOnCmd_SBMU18_03 0 "请求正常下高压" 1 "请求上高压" 2 "强制SBMU下高压" ;
VAL_ 2148630419 HvPwrOnCmd_SBMU19_03 0 "请求正常下高压" 1 "请求上高压" 2 "强制SBMU下高压" ;
VAL_ 2148630419 HvPwrOnCmd_SBMU20_03 0 "请求正常下高压" 1 "请求上高压" 2 "强制SBMU下高压" ;
VAL_ 2148630419 HvPwrOnCmd_SBMU21_03 0 "请求正常下高压" 1 "请求上高压" 2 "强制SBMU下高压" ;
VAL_ 2148630419 HvPwrOnCmd_SBMU22_03 0 "请求正常下高压" 1 "请求上高压" 2 "强制SBMU下高压" ;
VAL_ 2148630419 HvPwrOnCmd_SBMU23_03 0 "请求正常下高压" 1 "请求上高压" 2 "强制SBMU下高压" ;
VAL_ 2148630419 HvPwrOnCmd_SBMU24_03 0 "请求正常下高压" 1 "请求上高压" 2 "强制SBMU下高压" ;
VAL_ 2148630419 HvPwrOnCmd_SBMU25_03 0 "请求正常下高压" 1 "请求上高压" 2 "强制SBMU下高压" ;
VAL_ 2148630419 HvPwrOnCmd_SBMU26_03 0 "请求正常下高压" 1 "请求上高压" 2 "强制SBMU下高压" ;
VAL_ 2148630419 HvPwrOnCmd_SBMU27_03 0 "请求正常下高压" 1 "请求上高压" 2 "强制SBMU下高压" ;
VAL_ 2148630419 HvPwrOnCmd_SBMU28_03 0 "请求正常下高压" 1 "请求上高压" 2 "强制SBMU下高压" ;
VAL_ 2148630419 HvPwrOnCmd_SBMU29_03 0 "请求正常下高压" 1 "请求上高压" 2 "强制SBMU下高压" ;
VAL_ 2148630419 HvPwrOnCmd_SBMU30_03 0 "请求正常下高压" 1 "请求上高压" 2 "强制SBMU下高压" ;
VAL_ 2148630419 HvPwrOnCmd_SBMU31_03 0 "请求正常下高压" 1 "请求上高压" 2 "强制SBMU下高压" ;
VAL_ 2148630419 HvPwrOnCmd_SBMU32_03 0 "请求正常下高压" 1 "请求上高压" 2 "强制SBMU下高压" ;
VAL_ 2148630420 HvPwrOnCmd_SBMU01_04 0 "请求正常下高压" 1 "请求上高压" 2 "强制SBMU下高压" ;
VAL_ 2148630420 HvPwrOnCmd_SBMU02_04 0 "请求正常下高压" 1 "请求上高压" 2 "强制SBMU下高压" ;
VAL_ 2148630420 HvPwrOnCmd_SBMU03_04 0 "请求正常下高压" 1 "请求上高压" 2 "强制SBMU下高压" ;
VAL_ 2148630420 HvPwrOnCmd_SBMU04_04 0 "请求正常下高压" 1 "请求上高压" 2 "强制SBMU下高压" ;
VAL_ 2148630420 HvPwrOnCmd_SBMU05_04 0 "请求正常下高压" 1 "请求上高压" 2 "强制SBMU下高压" ;
VAL_ 2148630420 HvPwrOnCmd_SBMU06_04 0 "请求正常下高压" 1 "请求上高压" 2 "强制SBMU下高压" ;
VAL_ 2148630420 HvPwrOnCmd_SBMU07_04 0 "请求正常下高压" 1 "请求上高压" 2 "强制SBMU下高压" ;
VAL_ 2148630420 HvPwrOnCmd_SBMU08_04 0 "请求正常下高压" 1 "请求上高压" 2 "强制SBMU下高压" ;
VAL_ 2148630420 HvPwrOnCmd_SBMU09_04 0 "请求正常下高压" 1 "请求上高压" 2 "强制SBMU下高压" ;
VAL_ 2148630420 HvPwrOnCmd_SBMU10_04 0 "请求正常下高压" 1 "请求上高压" 2 "强制SBMU下高压" ;
VAL_ 2148630420 HvPwrOnCmd_SBMU11_04 0 "请求正常下高压" 1 "请求上高压" 2 "强制SBMU下高压" ;
VAL_ 2148630420 HvPwrOnCmd_SBMU12_04 0 "请求正常下高压" 1 "请求上高压" 2 "强制SBMU下高压" ;
VAL_ 2148630420 HvPwrOnCmd_SBMU13_04 0 "请求正常下高压" 1 "请求上高压" 2 "强制SBMU下高压" ;
VAL_ 2148630420 HvPwrOnCmd_SBMU14_04 0 "请求正常下高压" 1 "请求上高压" 2 "强制SBMU下高压" ;
VAL_ 2148630420 HvPwrOnCmd_SBMU15_04 0 "请求正常下高压" 1 "请求上高压" 2 "强制SBMU下高压" ;
VAL_ 2148630420 HvPwrOnCmd_SBMU16_04 0 "请求正常下高压" 1 "请求上高压" 2 "强制SBMU下高压" ;
VAL_ 2148630420 HvPwrOnCmd_SBMU17_04 0 "请求正常下高压" 1 "请求上高压" 2 "强制SBMU下高压" ;
VAL_ 2148630420 HvPwrOnCmd_SBMU18_04 0 "请求正常下高压" 1 "请求上高压" 2 "强制SBMU下高压" ;
VAL_ 2148630420 HvPwrOnCmd_SBMU19_04 0 "请求正常下高压" 1 "请求上高压" 2 "强制SBMU下高压" ;
VAL_ 2148630420 HvPwrOnCmd_SBMU20_04 0 "请求正常下高压" 1 "请求上高压" 2 "强制SBMU下高压" ;
VAL_ 2148630420 HvPwrOnCmd_SBMU21_04 0 "请求正常下高压" 1 "请求上高压" 2 "强制SBMU下高压" ;
VAL_ 2148630420 HvPwrOnCmd_SBMU22_04 0 "请求正常下高压" 1 "请求上高压" 2 "强制SBMU下高压" ;
VAL_ 2148630420 HvPwrOnCmd_SBMU23_04 0 "请求正常下高压" 1 "请求上高压" 2 "强制SBMU下高压" ;
VAL_ 2148630420 HvPwrOnCmd_SBMU24_04 0 "请求正常下高压" 1 "请求上高压" 2 "强制SBMU下高压" ;
VAL_ 2148630420 HvPwrOnCmd_SBMU25_04 0 "请求正常下高压" 1 "请求上高压" 2 "强制SBMU下高压" ;
VAL_ 2148630420 HvPwrOnCmd_SBMU26_04 0 "请求正常下高压" 1 "请求上高压" 2 "强制SBMU下高压" ;
VAL_ 2148630420 HvPwrOnCmd_SBMU27_04 0 "请求正常下高压" 1 "请求上高压" 2 "强制SBMU下高压" ;
VAL_ 2148630420 HvPwrOnCmd_SBMU28_04 0 "请求正常下高压" 1 "请求上高压" 2 "强制SBMU下高压" ;
VAL_ 2148630420 HvPwrOnCmd_SBMU29_04 0 "请求正常下高压" 1 "请求上高压" 2 "强制SBMU下高压" ;
VAL_ 2148630420 HvPwrOnCmd_SBMU30_04 0 "请求正常下高压" 1 "请求上高压" 2 "强制SBMU下高压" ;
VAL_ 2148630420 HvPwrOnCmd_SBMU31_04 0 "请求正常下高压" 1 "请求上高压" 2 "强制SBMU下高压" ;
VAL_ 2148630420 HvPwrOnCmd_SBMU32_04 0 "请求正常下高压" 1 "请求上高压" 2 "强制SBMU下高压" ;
VAL_ 2148630421 HvPwrOnCmd_SBMU01_05 0 "请求正常下高压" 1 "请求上高压" 2 "强制SBMU下高压" ;
VAL_ 2148630421 HvPwrOnCmd_SBMU02_05 0 "请求正常下高压" 1 "请求上高压" 2 "强制SBMU下高压" ;
VAL_ 2148630421 HvPwrOnCmd_SBMU03_05 0 "请求正常下高压" 1 "请求上高压" 2 "强制SBMU下高压" ;
VAL_ 2148630421 HvPwrOnCmd_SBMU04_05 0 "请求正常下高压" 1 "请求上高压" 2 "强制SBMU下高压" ;
VAL_ 2148630421 HvPwrOnCmd_SBMU05_05 0 "请求正常下高压" 1 "请求上高压" 2 "强制SBMU下高压" ;
VAL_ 2148630421 HvPwrOnCmd_SBMU06_05 0 "请求正常下高压" 1 "请求上高压" 2 "强制SBMU下高压" ;
VAL_ 2148630421 HvPwrOnCmd_SBMU07_05 0 "请求正常下高压" 1 "请求上高压" 2 "强制SBMU下高压" ;
VAL_ 2148630421 HvPwrOnCmd_SBMU08_05 0 "请求正常下高压" 1 "请求上高压" 2 "强制SBMU下高压" ;
VAL_ 2148630421 HvPwrOnCmd_SBMU09_05 0 "请求正常下高压" 1 "请求上高压" 2 "强制SBMU下高压" ;
VAL_ 2148630421 HvPwrOnCmd_SBMU10_05 0 "请求正常下高压" 1 "请求上高压" 2 "强制SBMU下高压" ;
VAL_ 2148630421 HvPwrOnCmd_SBMU11_05 0 "请求正常下高压" 1 "请求上高压" 2 "强制SBMU下高压" ;
VAL_ 2148630421 HvPwrOnCmd_SBMU12_05 0 "请求正常下高压" 1 "请求上高压" 2 "强制SBMU下高压" ;
VAL_ 2148630421 HvPwrOnCmd_SBMU13_05 0 "请求正常下高压" 1 "请求上高压" 2 "强制SBMU下高压" ;
VAL_ 2148630421 HvPwrOnCmd_SBMU14_05 0 "请求正常下高压" 1 "请求上高压" 2 "强制SBMU下高压" ;
VAL_ 2148630421 HvPwrOnCmd_SBMU15_05 0 "请求正常下高压" 1 "请求上高压" 2 "强制SBMU下高压" ;
VAL_ 2148630421 HvPwrOnCmd_SBMU16_05 0 "请求正常下高压" 1 "请求上高压" 2 "强制SBMU下高压" ;
VAL_ 2148630421 HvPwrOnCmd_SBMU17_05 0 "请求正常下高压" 1 "请求上高压" 2 "强制SBMU下高压" ;
VAL_ 2148630421 HvPwrOnCmd_SBMU18_05 0 "请求正常下高压" 1 "请求上高压" 2 "强制SBMU下高压" ;
VAL_ 2148630421 HvPwrOnCmd_SBMU19_05 0 "请求正常下高压" 1 "请求上高压" 2 "强制SBMU下高压" ;
VAL_ 2148630421 HvPwrOnCmd_SBMU20_05 0 "请求正常下高压" 1 "请求上高压" 2 "强制SBMU下高压" ;
VAL_ 2148630421 HvPwrOnCmd_SBMU21_05 0 "请求正常下高压" 1 "请求上高压" 2 "强制SBMU下高压" ;
VAL_ 2148630421 HvPwrOnCmd_SBMU22_05 0 "请求正常下高压" 1 "请求上高压" 2 "强制SBMU下高压" ;
VAL_ 2148630421 HvPwrOnCmd_SBMU23_05 0 "请求正常下高压" 1 "请求上高压" 2 "强制SBMU下高压" ;
VAL_ 2148630421 HvPwrOnCmd_SBMU24_05 0 "请求正常下高压" 1 "请求上高压" 2 "强制SBMU下高压" ;
VAL_ 2148630421 HvPwrOnCmd_SBMU25_05 0 "请求正常下高压" 1 "请求上高压" 2 "强制SBMU下高压" ;
VAL_ 2148630421 HvPwrOnCmd_SBMU26_05 0 "请求正常下高压" 1 "请求上高压" 2 "强制SBMU下高压" ;
VAL_ 2148630421 HvPwrOnCmd_SBMU27_05 0 "请求正常下高压" 1 "请求上高压" 2 "强制SBMU下高压" ;
VAL_ 2148630421 HvPwrOnCmd_SBMU28_05 0 "请求正常下高压" 1 "请求上高压" 2 "强制SBMU下高压" ;
VAL_ 2148630421 HvPwrOnCmd_SBMU29_05 0 "请求正常下高压" 1 "请求上高压" 2 "强制SBMU下高压" ;
VAL_ 2148630421 HvPwrOnCmd_SBMU30_05 0 "请求正常下高压" 1 "请求上高压" 2 "强制SBMU下高压" ;
VAL_ 2148630421 HvPwrOnCmd_SBMU31_05 0 "请求正常下高压" 1 "请求上高压" 2 "强制SBMU下高压" ;
VAL_ 2148630421 HvPwrOnCmd_SBMU32_05 0 "请求正常下高压" 1 "请求上高压" 2 "强制SBMU下高压" ;
VAL_ 2148630422 HvPwrOnCmd_SBMU01_06 0 "请求正常下高压" 1 "请求上高压" 2 "强制SBMU下高压" ;
VAL_ 2148630422 HvPwrOnCmd_SBMU02_06 0 "请求正常下高压" 1 "请求上高压" 2 "强制SBMU下高压" ;
VAL_ 2148630422 HvPwrOnCmd_SBMU03_06 0 "请求正常下高压" 1 "请求上高压" 2 "强制SBMU下高压" ;
VAL_ 2148630422 HvPwrOnCmd_SBMU04_06 0 "请求正常下高压" 1 "请求上高压" 2 "强制SBMU下高压" ;
VAL_ 2148630422 HvPwrOnCmd_SBMU05_06 0 "请求正常下高压" 1 "请求上高压" 2 "强制SBMU下高压" ;
VAL_ 2148630422 HvPwrOnCmd_SBMU06_06 0 "请求正常下高压" 1 "请求上高压" 2 "强制SBMU下高压" ;
VAL_ 2148630422 HvPwrOnCmd_SBMU07_06 0 "请求正常下高压" 1 "请求上高压" 2 "强制SBMU下高压" ;
VAL_ 2148630422 HvPwrOnCmd_SBMU08_06 0 "请求正常下高压" 1 "请求上高压" 2 "强制SBMU下高压" ;
VAL_ 2148630422 HvPwrOnCmd_SBMU09_06 0 "请求正常下高压" 1 "请求上高压" 2 "强制SBMU下高压" ;
VAL_ 2148630422 HvPwrOnCmd_SBMU10_06 0 "请求正常下高压" 1 "请求上高压" 2 "强制SBMU下高压" ;
VAL_ 2148630422 HvPwrOnCmd_SBMU11_06 0 "请求正常下高压" 1 "请求上高压" 2 "强制SBMU下高压" ;
VAL_ 2148630422 HvPwrOnCmd_SBMU12_06 0 "请求正常下高压" 1 "请求上高压" 2 "强制SBMU下高压" ;
VAL_ 2148630422 HvPwrOnCmd_SBMU13_06 0 "请求正常下高压" 1 "请求上高压" 2 "强制SBMU下高压" ;
VAL_ 2148630422 HvPwrOnCmd_SBMU14_06 0 "请求正常下高压" 1 "请求上高压" 2 "强制SBMU下高压" ;
VAL_ 2148630422 HvPwrOnCmd_SBMU15_06 0 "请求正常下高压" 1 "请求上高压" 2 "强制SBMU下高压" ;
VAL_ 2148630422 HvPwrOnCmd_SBMU16_06 0 "请求正常下高压" 1 "请求上高压" 2 "强制SBMU下高压" ;
VAL_ 2148630422 HvPwrOnCmd_SBMU17_06 0 "请求正常下高压" 1 "请求上高压" 2 "强制SBMU下高压" ;
VAL_ 2148630422 HvPwrOnCmd_SBMU18_06 0 "请求正常下高压" 1 "请求上高压" 2 "强制SBMU下高压" ;
VAL_ 2148630422 HvPwrOnCmd_SBMU19_06 0 "请求正常下高压" 1 "请求上高压" 2 "强制SBMU下高压" ;
VAL_ 2148630422 HvPwrOnCmd_SBMU20_06 0 "请求正常下高压" 1 "请求上高压" 2 "强制SBMU下高压" ;
VAL_ 2148630422 HvPwrOnCmd_SBMU21_06 0 "请求正常下高压" 1 "请求上高压" 2 "强制SBMU下高压" ;
VAL_ 2148630422 HvPwrOnCmd_SBMU22_06 0 "请求正常下高压" 1 "请求上高压" 2 "强制SBMU下高压" ;
VAL_ 2148630422 HvPwrOnCmd_SBMU23_06 0 "请求正常下高压" 1 "请求上高压" 2 "强制SBMU下高压" ;
VAL_ 2148630422 HvPwrOnCmd_SBMU24_06 0 "请求正常下高压" 1 "请求上高压" 2 "强制SBMU下高压" ;
VAL_ 2148630422 HvPwrOnCmd_SBMU25_06 0 "请求正常下高压" 1 "请求上高压" 2 "强制SBMU下高压" ;
VAL_ 2148630422 HvPwrOnCmd_SBMU26_06 0 "请求正常下高压" 1 "请求上高压" 2 "强制SBMU下高压" ;
VAL_ 2148630422 HvPwrOnCmd_SBMU27_06 0 "请求正常下高压" 1 "请求上高压" 2 "强制SBMU下高压" ;
VAL_ 2148630422 HvPwrOnCmd_SBMU28_06 0 "请求正常下高压" 1 "请求上高压" 2 "强制SBMU下高压" ;
VAL_ 2148630422 HvPwrOnCmd_SBMU29_06 0 "请求正常下高压" 1 "请求上高压" 2 "强制SBMU下高压" ;
VAL_ 2148630422 HvPwrOnCmd_SBMU30_06 0 "请求正常下高压" 1 "请求上高压" 2 "强制SBMU下高压" ;
VAL_ 2148630422 HvPwrOnCmd_SBMU31_06 0 "请求正常下高压" 1 "请求上高压" 2 "强制SBMU下高压" ;
VAL_ 2148630422 HvPwrOnCmd_SBMU32_06 0 "请求正常下高压" 1 "请求上高压" 2 "强制SBMU下高压" ;
VAL_ 2148630423 HvPwrOnCmd_SBMU01_07 0 "请求正常下高压" 1 "请求上高压" 2 "强制SBMU下高压" ;
VAL_ 2148630423 HvPwrOnCmd_SBMU02_07 0 "请求正常下高压" 1 "请求上高压" 2 "强制SBMU下高压" ;
VAL_ 2148630423 HvPwrOnCmd_SBMU03_07 0 "请求正常下高压" 1 "请求上高压" 2 "强制SBMU下高压" ;
VAL_ 2148630423 HvPwrOnCmd_SBMU04_07 0 "请求正常下高压" 1 "请求上高压" 2 "强制SBMU下高压" ;
VAL_ 2148630423 HvPwrOnCmd_SBMU05_07 0 "请求正常下高压" 1 "请求上高压" 2 "强制SBMU下高压" ;
VAL_ 2148630423 HvPwrOnCmd_SBMU06_07 0 "请求正常下高压" 1 "请求上高压" 2 "强制SBMU下高压" ;
VAL_ 2148630423 HvPwrOnCmd_SBMU07_07 0 "请求正常下高压" 1 "请求上高压" 2 "强制SBMU下高压" ;
VAL_ 2148630423 HvPwrOnCmd_SBMU08_07 0 "请求正常下高压" 1 "请求上高压" 2 "强制SBMU下高压" ;
VAL_ 2148630423 HvPwrOnCmd_SBMU09_07 0 "请求正常下高压" 1 "请求上高压" 2 "强制SBMU下高压" ;
VAL_ 2148630423 HvPwrOnCmd_SBMU10_07 0 "请求正常下高压" 1 "请求上高压" 2 "强制SBMU下高压" ;
VAL_ 2148630423 HvPwrOnCmd_SBMU11_07 0 "请求正常下高压" 1 "请求上高压" 2 "强制SBMU下高压" ;
VAL_ 2148630423 HvPwrOnCmd_SBMU12_07 0 "请求正常下高压" 1 "请求上高压" 2 "强制SBMU下高压" ;
VAL_ 2148630423 HvPwrOnCmd_SBMU13_07 0 "请求正常下高压" 1 "请求上高压" 2 "强制SBMU下高压" ;
VAL_ 2148630423 HvPwrOnCmd_SBMU14_07 0 "请求正常下高压" 1 "请求上高压" 2 "强制SBMU下高压" ;
VAL_ 2148630423 HvPwrOnCmd_SBMU15_07 0 "请求正常下高压" 1 "请求上高压" 2 "强制SBMU下高压" ;
VAL_ 2148630423 HvPwrOnCmd_SBMU16_07 0 "请求正常下高压" 1 "请求上高压" 2 "强制SBMU下高压" ;
VAL_ 2148630423 HvPwrOnCmd_SBMU17_07 0 "请求正常下高压" 1 "请求上高压" 2 "强制SBMU下高压" ;
VAL_ 2148630423 HvPwrOnCmd_SBMU18_07 0 "请求正常下高压" 1 "请求上高压" 2 "强制SBMU下高压" ;
VAL_ 2148630423 HvPwrOnCmd_SBMU19_07 0 "请求正常下高压" 1 "请求上高压" 2 "强制SBMU下高压" ;
VAL_ 2148630423 HvPwrOnCmd_SBMU20_07 0 "请求正常下高压" 1 "请求上高压" 2 "强制SBMU下高压" ;
VAL_ 2148630423 HvPwrOnCmd_SBMU21_07 0 "请求正常下高压" 1 "请求上高压" 2 "强制SBMU下高压" ;
VAL_ 2148630423 HvPwrOnCmd_SBMU22_07 0 "请求正常下高压" 1 "请求上高压" 2 "强制SBMU下高压" ;
VAL_ 2148630423 HvPwrOnCmd_SBMU23_07 0 "请求正常下高压" 1 "请求上高压" 2 "强制SBMU下高压" ;
VAL_ 2148630423 HvPwrOnCmd_SBMU24_07 0 "请求正常下高压" 1 "请求上高压" 2 "强制SBMU下高压" ;
VAL_ 2148630423 HvPwrOnCmd_SBMU25_07 0 "请求正常下高压" 1 "请求上高压" 2 "强制SBMU下高压" ;
VAL_ 2148630423 HvPwrOnCmd_SBMU26_07 0 "请求正常下高压" 1 "请求上高压" 2 "强制SBMU下高压" ;
VAL_ 2148630423 HvPwrOnCmd_SBMU27_07 0 "请求正常下高压" 1 "请求上高压" 2 "强制SBMU下高压" ;
VAL_ 2148630423 HvPwrOnCmd_SBMU28_07 0 "请求正常下高压" 1 "请求上高压" 2 "强制SBMU下高压" ;
VAL_ 2148630423 HvPwrOnCmd_SBMU29_07 0 "请求正常下高压" 1 "请求上高压" 2 "强制SBMU下高压" ;
VAL_ 2148630423 HvPwrOnCmd_SBMU30_07 0 "请求正常下高压" 1 "请求上高压" 2 "强制SBMU下高压" ;
VAL_ 2148630423 HvPwrOnCmd_SBMU31_07 0 "请求正常下高压" 1 "请求上高压" 2 "强制SBMU下高压" ;
VAL_ 2148630423 HvPwrOnCmd_SBMU32_07 0 "请求正常下高压" 1 "请求上高压" 2 "强制SBMU下高压" ;
VAL_ 2148630424 HvPwrOnCmd_SBMU01_08 0 "请求正常下高压" 1 "请求上高压" 2 "强制SBMU下高压" ;
VAL_ 2148630424 HvPwrOnCmd_SBMU02_08 0 "请求正常下高压" 1 "请求上高压" 2 "强制SBMU下高压" ;
VAL_ 2148630424 HvPwrOnCmd_SBMU03_08 0 "请求正常下高压" 1 "请求上高压" 2 "强制SBMU下高压" ;
VAL_ 2148630424 HvPwrOnCmd_SBMU04_08 0 "请求正常下高压" 1 "请求上高压" 2 "强制SBMU下高压" ;
VAL_ 2148630424 HvPwrOnCmd_SBMU05_08 0 "请求正常下高压" 1 "请求上高压" 2 "强制SBMU下高压" ;
VAL_ 2148630424 HvPwrOnCmd_SBMU06_08 0 "请求正常下高压" 1 "请求上高压" 2 "强制SBMU下高压" ;
VAL_ 2148630424 HvPwrOnCmd_SBMU07_08 0 "请求正常下高压" 1 "请求上高压" 2 "强制SBMU下高压" ;
VAL_ 2148630424 HvPwrOnCmd_SBMU08_08 0 "请求正常下高压" 1 "请求上高压" 2 "强制SBMU下高压" ;
VAL_ 2148630424 HvPwrOnCmd_SBMU09_08 0 "请求正常下高压" 1 "请求上高压" 2 "强制SBMU下高压" ;
VAL_ 2148630424 HvPwrOnCmd_SBMU10_08 0 "请求正常下高压" 1 "请求上高压" 2 "强制SBMU下高压" ;
VAL_ 2148630424 HvPwrOnCmd_SBMU11_08 0 "请求正常下高压" 1 "请求上高压" 2 "强制SBMU下高压" ;
VAL_ 2148630424 HvPwrOnCmd_SBMU12_08 0 "请求正常下高压" 1 "请求上高压" 2 "强制SBMU下高压" ;
VAL_ 2148630424 HvPwrOnCmd_SBMU13_08 0 "请求正常下高压" 1 "请求上高压" 2 "强制SBMU下高压" ;
VAL_ 2148630424 HvPwrOnCmd_SBMU14_08 0 "请求正常下高压" 1 "请求上高压" 2 "强制SBMU下高压" ;
VAL_ 2148630424 HvPwrOnCmd_SBMU15_08 0 "请求正常下高压" 1 "请求上高压" 2 "强制SBMU下高压" ;
VAL_ 2148630424 HvPwrOnCmd_SBMU16_08 0 "请求正常下高压" 1 "请求上高压" 2 "强制SBMU下高压" ;
VAL_ 2148630424 HvPwrOnCmd_SBMU17_08 0 "请求正常下高压" 1 "请求上高压" 2 "强制SBMU下高压" ;
VAL_ 2148630424 HvPwrOnCmd_SBMU18_08 0 "请求正常下高压" 1 "请求上高压" 2 "强制SBMU下高压" ;
VAL_ 2148630424 HvPwrOnCmd_SBMU19_08 0 "请求正常下高压" 1 "请求上高压" 2 "强制SBMU下高压" ;
VAL_ 2148630424 HvPwrOnCmd_SBMU20_08 0 "请求正常下高压" 1 "请求上高压" 2 "强制SBMU下高压" ;
VAL_ 2148630424 HvPwrOnCmd_SBMU21_08 0 "请求正常下高压" 1 "请求上高压" 2 "强制SBMU下高压" ;
VAL_ 2148630424 HvPwrOnCmd_SBMU22_08 0 "请求正常下高压" 1 "请求上高压" 2 "强制SBMU下高压" ;
VAL_ 2148630424 HvPwrOnCmd_SBMU23_08 0 "请求正常下高压" 1 "请求上高压" 2 "强制SBMU下高压" ;
VAL_ 2148630424 HvPwrOnCmd_SBMU24_08 0 "请求正常下高压" 1 "请求上高压" 2 "强制SBMU下高压" ;
VAL_ 2148630424 HvPwrOnCmd_SBMU25_08 0 "请求正常下高压" 1 "请求上高压" 2 "强制SBMU下高压" ;
VAL_ 2148630424 HvPwrOnCmd_SBMU26_08 0 "请求正常下高压" 1 "请求上高压" 2 "强制SBMU下高压" ;
VAL_ 2148630424 HvPwrOnCmd_SBMU27_08 0 "请求正常下高压" 1 "请求上高压" 2 "强制SBMU下高压" ;
VAL_ 2148630424 HvPwrOnCmd_SBMU28_08 0 "请求正常下高压" 1 "请求上高压" 2 "强制SBMU下高压" ;
VAL_ 2148630424 HvPwrOnCmd_SBMU29_08 0 "请求正常下高压" 1 "请求上高压" 2 "强制SBMU下高压" ;
VAL_ 2148630424 HvPwrOnCmd_SBMU30_08 0 "请求正常下高压" 1 "请求上高压" 2 "强制SBMU下高压" ;
VAL_ 2148630424 HvPwrOnCmd_SBMU31_08 0 "请求正常下高压" 1 "请求上高压" 2 "强制SBMU下高压" ;
VAL_ 2148630424 HvPwrOnCmd_SBMU32_08 0 "请求正常下高压" 1 "请求上高压" 2 "强制SBMU下高压" ;
VAL_ 2148630425 HvPwrOnCmd_SBMU01_09 0 "请求正常下高压" 1 "请求上高压" 2 "强制SBMU下高压" ;
VAL_ 2148630425 HvPwrOnCmd_SBMU02_09 0 "请求正常下高压" 1 "请求上高压" 2 "强制SBMU下高压" ;
VAL_ 2148630425 HvPwrOnCmd_SBMU03_09 0 "请求正常下高压" 1 "请求上高压" 2 "强制SBMU下高压" ;
VAL_ 2148630425 HvPwrOnCmd_SBMU04_09 0 "请求正常下高压" 1 "请求上高压" 2 "强制SBMU下高压" ;
VAL_ 2148630425 HvPwrOnCmd_SBMU05_09 0 "请求正常下高压" 1 "请求上高压" 2 "强制SBMU下高压" ;
VAL_ 2148630425 HvPwrOnCmd_SBMU06_09 0 "请求正常下高压" 1 "请求上高压" 2 "强制SBMU下高压" ;
VAL_ 2148630425 HvPwrOnCmd_SBMU07_09 0 "请求正常下高压" 1 "请求上高压" 2 "强制SBMU下高压" ;
VAL_ 2148630425 HvPwrOnCmd_SBMU08_09 0 "请求正常下高压" 1 "请求上高压" 2 "强制SBMU下高压" ;
VAL_ 2148630425 HvPwrOnCmd_SBMU09_09 0 "请求正常下高压" 1 "请求上高压" 2 "强制SBMU下高压" ;
VAL_ 2148630425 HvPwrOnCmd_SBMU10_09 0 "请求正常下高压" 1 "请求上高压" 2 "强制SBMU下高压" ;
VAL_ 2148630425 HvPwrOnCmd_SBMU11_09 0 "请求正常下高压" 1 "请求上高压" 2 "强制SBMU下高压" ;
VAL_ 2148630425 HvPwrOnCmd_SBMU12_09 0 "请求正常下高压" 1 "请求上高压" 2 "强制SBMU下高压" ;
VAL_ 2148630425 HvPwrOnCmd_SBMU13_09 0 "请求正常下高压" 1 "请求上高压" 2 "强制SBMU下高压" ;
VAL_ 2148630425 HvPwrOnCmd_SBMU14_09 0 "请求正常下高压" 1 "请求上高压" 2 "强制SBMU下高压" ;
VAL_ 2148630425 HvPwrOnCmd_SBMU15_09 0 "请求正常下高压" 1 "请求上高压" 2 "强制SBMU下高压" ;
VAL_ 2148630425 HvPwrOnCmd_SBMU16_09 0 "请求正常下高压" 1 "请求上高压" 2 "强制SBMU下高压" ;
VAL_ 2148630425 HvPwrOnCmd_SBMU17_09 0 "请求正常下高压" 1 "请求上高压" 2 "强制SBMU下高压" ;
VAL_ 2148630425 HvPwrOnCmd_SBMU18_09 0 "请求正常下高压" 1 "请求上高压" 2 "强制SBMU下高压" ;
VAL_ 2148630425 HvPwrOnCmd_SBMU19_09 0 "请求正常下高压" 1 "请求上高压" 2 "强制SBMU下高压" ;
VAL_ 2148630425 HvPwrOnCmd_SBMU20_09 0 "请求正常下高压" 1 "请求上高压" 2 "强制SBMU下高压" ;
VAL_ 2148630425 HvPwrOnCmd_SBMU21_09 0 "请求正常下高压" 1 "请求上高压" 2 "强制SBMU下高压" ;
VAL_ 2148630425 HvPwrOnCmd_SBMU22_09 0 "请求正常下高压" 1 "请求上高压" 2 "强制SBMU下高压" ;
VAL_ 2148630425 HvPwrOnCmd_SBMU23_09 0 "请求正常下高压" 1 "请求上高压" 2 "强制SBMU下高压" ;
VAL_ 2148630425 HvPwrOnCmd_SBMU24_09 0 "请求正常下高压" 1 "请求上高压" 2 "强制SBMU下高压" ;
VAL_ 2148630425 HvPwrOnCmd_SBMU25_09 0 "请求正常下高压" 1 "请求上高压" 2 "强制SBMU下高压" ;
VAL_ 2148630425 HvPwrOnCmd_SBMU26_09 0 "请求正常下高压" 1 "请求上高压" 2 "强制SBMU下高压" ;
VAL_ 2148630425 HvPwrOnCmd_SBMU27_09 0 "请求正常下高压" 1 "请求上高压" 2 "强制SBMU下高压" ;
VAL_ 2148630425 HvPwrOnCmd_SBMU28_09 0 "请求正常下高压" 1 "请求上高压" 2 "强制SBMU下高压" ;
VAL_ 2148630425 HvPwrOnCmd_SBMU29_09 0 "请求正常下高压" 1 "请求上高压" 2 "强制SBMU下高压" ;
VAL_ 2148630425 HvPwrOnCmd_SBMU30_09 0 "请求正常下高压" 1 "请求上高压" 2 "强制SBMU下高压" ;
VAL_ 2148630425 HvPwrOnCmd_SBMU31_09 0 "请求正常下高压" 1 "请求上高压" 2 "强制SBMU下高压" ;
VAL_ 2148630425 HvPwrOnCmd_SBMU32_09 0 "请求正常下高压" 1 "请求上高压" 2 "强制SBMU下高压" ;
VAL_ 2148630426 HvPwrOnCmd_SBMU01_10 0 "请求正常下高压" 1 "请求上高压" 2 "强制SBMU下高压" ;
VAL_ 2148630426 HvPwrOnCmd_SBMU02_10 0 "请求正常下高压" 1 "请求上高压" 2 "强制SBMU下高压" ;
VAL_ 2148630426 HvPwrOnCmd_SBMU03_10 0 "请求正常下高压" 1 "请求上高压" 2 "强制SBMU下高压" ;
VAL_ 2148630426 HvPwrOnCmd_SBMU04_10 0 "请求正常下高压" 1 "请求上高压" 2 "强制SBMU下高压" ;
VAL_ 2148630426 HvPwrOnCmd_SBMU05_10 0 "请求正常下高压" 1 "请求上高压" 2 "强制SBMU下高压" ;
VAL_ 2148630426 HvPwrOnCmd_SBMU06_10 0 "请求正常下高压" 1 "请求上高压" 2 "强制SBMU下高压" ;
VAL_ 2148630426 HvPwrOnCmd_SBMU07_10 0 "请求正常下高压" 1 "请求上高压" 2 "强制SBMU下高压" ;
VAL_ 2148630426 HvPwrOnCmd_SBMU08_10 0 "请求正常下高压" 1 "请求上高压" 2 "强制SBMU下高压" ;
VAL_ 2148630426 HvPwrOnCmd_SBMU09_10 0 "请求正常下高压" 1 "请求上高压" 2 "强制SBMU下高压" ;
VAL_ 2148630426 HvPwrOnCmd_SBMU10_10 0 "请求正常下高压" 1 "请求上高压" 2 "强制SBMU下高压" ;
VAL_ 2148630426 HvPwrOnCmd_SBMU11_10 0 "请求正常下高压" 1 "请求上高压" 2 "强制SBMU下高压" ;
VAL_ 2148630426 HvPwrOnCmd_SBMU12_10 0 "请求正常下高压" 1 "请求上高压" 2 "强制SBMU下高压" ;
VAL_ 2148630426 HvPwrOnCmd_SBMU13_10 0 "请求正常下高压" 1 "请求上高压" 2 "强制SBMU下高压" ;
VAL_ 2148630426 HvPwrOnCmd_SBMU14_10 0 "请求正常下高压" 1 "请求上高压" 2 "强制SBMU下高压" ;
VAL_ 2148630426 HvPwrOnCmd_SBMU15_10 0 "请求正常下高压" 1 "请求上高压" 2 "强制SBMU下高压" ;
VAL_ 2148630426 HvPwrOnCmd_SBMU16_10 0 "请求正常下高压" 1 "请求上高压" 2 "强制SBMU下高压" ;
VAL_ 2148630426 HvPwrOnCmd_SBMU17_10 0 "请求正常下高压" 1 "请求上高压" 2 "强制SBMU下高压" ;
VAL_ 2148630426 HvPwrOnCmd_SBMU18_10 0 "请求正常下高压" 1 "请求上高压" 2 "强制SBMU下高压" ;
VAL_ 2148630426 HvPwrOnCmd_SBMU19_10 0 "请求正常下高压" 1 "请求上高压" 2 "强制SBMU下高压" ;
VAL_ 2148630426 HvPwrOnCmd_SBMU20_10 0 "请求正常下高压" 1 "请求上高压" 2 "强制SBMU下高压" ;
VAL_ 2148630426 HvPwrOnCmd_SBMU21_10 0 "请求正常下高压" 1 "请求上高压" 2 "强制SBMU下高压" ;
VAL_ 2148630426 HvPwrOnCmd_SBMU22_10 0 "请求正常下高压" 1 "请求上高压" 2 "强制SBMU下高压" ;
VAL_ 2148630426 HvPwrOnCmd_SBMU23_10 0 "请求正常下高压" 1 "请求上高压" 2 "强制SBMU下高压" ;
VAL_ 2148630426 HvPwrOnCmd_SBMU24_10 0 "请求正常下高压" 1 "请求上高压" 2 "强制SBMU下高压" ;
VAL_ 2148630426 HvPwrOnCmd_SBMU25_10 0 "请求正常下高压" 1 "请求上高压" 2 "强制SBMU下高压" ;
VAL_ 2148630426 HvPwrOnCmd_SBMU26_10 0 "请求正常下高压" 1 "请求上高压" 2 "强制SBMU下高压" ;
VAL_ 2148630426 HvPwrOnCmd_SBMU27_10 0 "请求正常下高压" 1 "请求上高压" 2 "强制SBMU下高压" ;
VAL_ 2148630426 HvPwrOnCmd_SBMU28_10 0 "请求正常下高压" 1 "请求上高压" 2 "强制SBMU下高压" ;
VAL_ 2148630426 HvPwrOnCmd_SBMU29_10 0 "请求正常下高压" 1 "请求上高压" 2 "强制SBMU下高压" ;
VAL_ 2148630426 HvPwrOnCmd_SBMU30_10 0 "请求正常下高压" 1 "请求上高压" 2 "强制SBMU下高压" ;
VAL_ 2148630426 HvPwrOnCmd_SBMU31_10 0 "请求正常下高压" 1 "请求上高压" 2 "强制SBMU下高压" ;
VAL_ 2148630426 HvPwrOnCmd_SBMU32_10 0 "请求正常下高压" 1 "请求上高压" 2 "强制SBMU下高压" ;
VAL_ 2148630427 HvPwrOnCmd_SBMU01_11 0 "请求正常下高压" 1 "请求上高压" 2 "强制SBMU下高压" ;
VAL_ 2148630427 HvPwrOnCmd_SBMU02_11 0 "请求正常下高压" 1 "请求上高压" 2 "强制SBMU下高压" ;
VAL_ 2148630427 HvPwrOnCmd_SBMU03_11 0 "请求正常下高压" 1 "请求上高压" 2 "强制SBMU下高压" ;
VAL_ 2148630427 HvPwrOnCmd_SBMU04_11 0 "请求正常下高压" 1 "请求上高压" 2 "强制SBMU下高压" ;
VAL_ 2148630427 HvPwrOnCmd_SBMU05_11 0 "请求正常下高压" 1 "请求上高压" 2 "强制SBMU下高压" ;
VAL_ 2148630427 HvPwrOnCmd_SBMU06_11 0 "请求正常下高压" 1 "请求上高压" 2 "强制SBMU下高压" ;
VAL_ 2148630427 HvPwrOnCmd_SBMU07_11 0 "请求正常下高压" 1 "请求上高压" 2 "强制SBMU下高压" ;
VAL_ 2148630427 HvPwrOnCmd_SBMU08_11 0 "请求正常下高压" 1 "请求上高压" 2 "强制SBMU下高压" ;
VAL_ 2148630427 HvPwrOnCmd_SBMU09_11 0 "请求正常下高压" 1 "请求上高压" 2 "强制SBMU下高压" ;
VAL_ 2148630427 HvPwrOnCmd_SBMU10_11 0 "请求正常下高压" 1 "请求上高压" 2 "强制SBMU下高压" ;
VAL_ 2148630427 HvPwrOnCmd_SBMU11_11 0 "请求正常下高压" 1 "请求上高压" 2 "强制SBMU下高压" ;
VAL_ 2148630427 HvPwrOnCmd_SBMU12_11 0 "请求正常下高压" 1 "请求上高压" 2 "强制SBMU下高压" ;
VAL_ 2148630427 HvPwrOnCmd_SBMU13_11 0 "请求正常下高压" 1 "请求上高压" 2 "强制SBMU下高压" ;
VAL_ 2148630427 HvPwrOnCmd_SBMU14_11 0 "请求正常下高压" 1 "请求上高压" 2 "强制SBMU下高压" ;
VAL_ 2148630427 HvPwrOnCmd_SBMU15_11 0 "请求正常下高压" 1 "请求上高压" 2 "强制SBMU下高压" ;
VAL_ 2148630427 HvPwrOnCmd_SBMU16_11 0 "请求正常下高压" 1 "请求上高压" 2 "强制SBMU下高压" ;
VAL_ 2148630427 HvPwrOnCmd_SBMU17_11 0 "请求正常下高压" 1 "请求上高压" 2 "强制SBMU下高压" ;
VAL_ 2148630427 HvPwrOnCmd_SBMU18_11 0 "请求正常下高压" 1 "请求上高压" 2 "强制SBMU下高压" ;
VAL_ 2148630427 HvPwrOnCmd_SBMU19_11 0 "请求正常下高压" 1 "请求上高压" 2 "强制SBMU下高压" ;
VAL_ 2148630427 HvPwrOnCmd_SBMU20_11 0 "请求正常下高压" 1 "请求上高压" 2 "强制SBMU下高压" ;
VAL_ 2148630427 HvPwrOnCmd_SBMU21_11 0 "请求正常下高压" 1 "请求上高压" 2 "强制SBMU下高压" ;
VAL_ 2148630427 HvPwrOnCmd_SBMU22_11 0 "请求正常下高压" 1 "请求上高压" 2 "强制SBMU下高压" ;
VAL_ 2148630427 HvPwrOnCmd_SBMU23_11 0 "请求正常下高压" 1 "请求上高压" 2 "强制SBMU下高压" ;
VAL_ 2148630427 HvPwrOnCmd_SBMU24_11 0 "请求正常下高压" 1 "请求上高压" 2 "强制SBMU下高压" ;
VAL_ 2148630427 HvPwrOnCmd_SBMU25_11 0 "请求正常下高压" 1 "请求上高压" 2 "强制SBMU下高压" ;
VAL_ 2148630427 HvPwrOnCmd_SBMU26_11 0 "请求正常下高压" 1 "请求上高压" 2 "强制SBMU下高压" ;
VAL_ 2148630427 HvPwrOnCmd_SBMU27_11 0 "请求正常下高压" 1 "请求上高压" 2 "强制SBMU下高压" ;
VAL_ 2148630427 HvPwrOnCmd_SBMU28_11 0 "请求正常下高压" 1 "请求上高压" 2 "强制SBMU下高压" ;
VAL_ 2148630427 HvPwrOnCmd_SBMU29_11 0 "请求正常下高压" 1 "请求上高压" 2 "强制SBMU下高压" ;
VAL_ 2148630427 HvPwrOnCmd_SBMU30_11 0 "请求正常下高压" 1 "请求上高压" 2 "强制SBMU下高压" ;
VAL_ 2148630427 HvPwrOnCmd_SBMU31_11 0 "请求正常下高压" 1 "请求上高压" 2 "强制SBMU下高压" ;
VAL_ 2148630427 HvPwrOnCmd_SBMU32_11 0 "请求正常下高压" 1 "请求上高压" 2 "强制SBMU下高压" ;
VAL_ 2148630428 HvPwrOnCmd_SBMU01_12 0 "请求正常下高压" 1 "请求上高压" 2 "强制SBMU下高压" ;
VAL_ 2148630428 HvPwrOnCmd_SBMU02_12 0 "请求正常下高压" 1 "请求上高压" 2 "强制SBMU下高压" ;
VAL_ 2148630428 HvPwrOnCmd_SBMU03_12 0 "请求正常下高压" 1 "请求上高压" 2 "强制SBMU下高压" ;
VAL_ 2148630428 HvPwrOnCmd_SBMU04_12 0 "请求正常下高压" 1 "请求上高压" 2 "强制SBMU下高压" ;
VAL_ 2148630428 HvPwrOnCmd_SBMU05_12 0 "请求正常下高压" 1 "请求上高压" 2 "强制SBMU下高压" ;
VAL_ 2148630428 HvPwrOnCmd_SBMU06_12 0 "请求正常下高压" 1 "请求上高压" 2 "强制SBMU下高压" ;
VAL_ 2148630428 HvPwrOnCmd_SBMU07_12 0 "请求正常下高压" 1 "请求上高压" 2 "强制SBMU下高压" ;
VAL_ 2148630428 HvPwrOnCmd_SBMU08_12 0 "请求正常下高压" 1 "请求上高压" 2 "强制SBMU下高压" ;
VAL_ 2148630428 HvPwrOnCmd_SBMU09_12 0 "请求正常下高压" 1 "请求上高压" 2 "强制SBMU下高压" ;
VAL_ 2148630428 HvPwrOnCmd_SBMU10_12 0 "请求正常下高压" 1 "请求上高压" 2 "强制SBMU下高压" ;
VAL_ 2148630428 HvPwrOnCmd_SBMU11_12 0 "请求正常下高压" 1 "请求上高压" 2 "强制SBMU下高压" ;
VAL_ 2148630428 HvPwrOnCmd_SBMU12_12 0 "请求正常下高压" 1 "请求上高压" 2 "强制SBMU下高压" ;
VAL_ 2148630428 HvPwrOnCmd_SBMU13_12 0 "请求正常下高压" 1 "请求上高压" 2 "强制SBMU下高压" ;
VAL_ 2148630428 HvPwrOnCmd_SBMU14_12 0 "请求正常下高压" 1 "请求上高压" 2 "强制SBMU下高压" ;
VAL_ 2148630428 HvPwrOnCmd_SBMU15_12 0 "请求正常下高压" 1 "请求上高压" 2 "强制SBMU下高压" ;
VAL_ 2148630428 HvPwrOnCmd_SBMU16_12 0 "请求正常下高压" 1 "请求上高压" 2 "强制SBMU下高压" ;
VAL_ 2148630428 HvPwrOnCmd_SBMU17_12 0 "请求正常下高压" 1 "请求上高压" 2 "强制SBMU下高压" ;
VAL_ 2148630428 HvPwrOnCmd_SBMU18_12 0 "请求正常下高压" 1 "请求上高压" 2 "强制SBMU下高压" ;
VAL_ 2148630428 HvPwrOnCmd_SBMU19_12 0 "请求正常下高压" 1 "请求上高压" 2 "强制SBMU下高压" ;
VAL_ 2148630428 HvPwrOnCmd_SBMU20_12 0 "请求正常下高压" 1 "请求上高压" 2 "强制SBMU下高压" ;
VAL_ 2148630428 HvPwrOnCmd_SBMU21_12 0 "请求正常下高压" 1 "请求上高压" 2 "强制SBMU下高压" ;
VAL_ 2148630428 HvPwrOnCmd_SBMU22_12 0 "请求正常下高压" 1 "请求上高压" 2 "强制SBMU下高压" ;
VAL_ 2148630428 HvPwrOnCmd_SBMU23_12 0 "请求正常下高压" 1 "请求上高压" 2 "强制SBMU下高压" ;
VAL_ 2148630428 HvPwrOnCmd_SBMU24_12 0 "请求正常下高压" 1 "请求上高压" 2 "强制SBMU下高压" ;
VAL_ 2148630428 HvPwrOnCmd_SBMU25_12 0 "请求正常下高压" 1 "请求上高压" 2 "强制SBMU下高压" ;
VAL_ 2148630428 HvPwrOnCmd_SBMU26_12 0 "请求正常下高压" 1 "请求上高压" 2 "强制SBMU下高压" ;
VAL_ 2148630428 HvPwrOnCmd_SBMU27_12 0 "请求正常下高压" 1 "请求上高压" 2 "强制SBMU下高压" ;
VAL_ 2148630428 HvPwrOnCmd_SBMU28_12 0 "请求正常下高压" 1 "请求上高压" 2 "强制SBMU下高压" ;
VAL_ 2148630428 HvPwrOnCmd_SBMU29_12 0 "请求正常下高压" 1 "请求上高压" 2 "强制SBMU下高压" ;
VAL_ 2148630428 HvPwrOnCmd_SBMU30_12 0 "请求正常下高压" 1 "请求上高压" 2 "强制SBMU下高压" ;
VAL_ 2148630428 HvPwrOnCmd_SBMU31_12 0 "请求正常下高压" 1 "请求上高压" 2 "强制SBMU下高压" ;
VAL_ 2148630428 HvPwrOnCmd_SBMU32_12 0 "请求正常下高压" 1 "请求上高压" 2 "强制SBMU下高压" ;
VAL_ 2148630429 HvPwrOnCmd_SBMU01_13 0 "请求正常下高压" 1 "请求上高压" 2 "强制SBMU下高压" ;
VAL_ 2148630429 HvPwrOnCmd_SBMU02_13 0 "请求正常下高压" 1 "请求上高压" 2 "强制SBMU下高压" ;
VAL_ 2148630429 HvPwrOnCmd_SBMU03_13 0 "请求正常下高压" 1 "请求上高压" 2 "强制SBMU下高压" ;
VAL_ 2148630429 HvPwrOnCmd_SBMU04_13 0 "请求正常下高压" 1 "请求上高压" 2 "强制SBMU下高压" ;
VAL_ 2148630429 HvPwrOnCmd_SBMU05_13 0 "请求正常下高压" 1 "请求上高压" 2 "强制SBMU下高压" ;
VAL_ 2148630429 HvPwrOnCmd_SBMU06_13 0 "请求正常下高压" 1 "请求上高压" 2 "强制SBMU下高压" ;
VAL_ 2148630429 HvPwrOnCmd_SBMU07_13 0 "请求正常下高压" 1 "请求上高压" 2 "强制SBMU下高压" ;
VAL_ 2148630429 HvPwrOnCmd_SBMU08_13 0 "请求正常下高压" 1 "请求上高压" 2 "强制SBMU下高压" ;
VAL_ 2148630429 HvPwrOnCmd_SBMU09_13 0 "请求正常下高压" 1 "请求上高压" 2 "强制SBMU下高压" ;
VAL_ 2148630429 HvPwrOnCmd_SBMU10_13 0 "请求正常下高压" 1 "请求上高压" 2 "强制SBMU下高压" ;
VAL_ 2148630429 HvPwrOnCmd_SBMU11_13 0 "请求正常下高压" 1 "请求上高压" 2 "强制SBMU下高压" ;
VAL_ 2148630429 HvPwrOnCmd_SBMU12_13 0 "请求正常下高压" 1 "请求上高压" 2 "强制SBMU下高压" ;
VAL_ 2148630429 HvPwrOnCmd_SBMU13_13 0 "请求正常下高压" 1 "请求上高压" 2 "强制SBMU下高压" ;
VAL_ 2148630429 HvPwrOnCmd_SBMU14_13 0 "请求正常下高压" 1 "请求上高压" 2 "强制SBMU下高压" ;
VAL_ 2148630429 HvPwrOnCmd_SBMU15_13 0 "请求正常下高压" 1 "请求上高压" 2 "强制SBMU下高压" ;
VAL_ 2148630429 HvPwrOnCmd_SBMU16_13 0 "请求正常下高压" 1 "请求上高压" 2 "强制SBMU下高压" ;
VAL_ 2148630429 HvPwrOnCmd_SBMU17_13 0 "请求正常下高压" 1 "请求上高压" 2 "强制SBMU下高压" ;
VAL_ 2148630429 HvPwrOnCmd_SBMU18_13 0 "请求正常下高压" 1 "请求上高压" 2 "强制SBMU下高压" ;
VAL_ 2148630429 HvPwrOnCmd_SBMU19_13 0 "请求正常下高压" 1 "请求上高压" 2 "强制SBMU下高压" ;
VAL_ 2148630429 HvPwrOnCmd_SBMU20_13 0 "请求正常下高压" 1 "请求上高压" 2 "强制SBMU下高压" ;
VAL_ 2148630429 HvPwrOnCmd_SBMU21_13 0 "请求正常下高压" 1 "请求上高压" 2 "强制SBMU下高压" ;
VAL_ 2148630429 HvPwrOnCmd_SBMU22_13 0 "请求正常下高压" 1 "请求上高压" 2 "强制SBMU下高压" ;
VAL_ 2148630429 HvPwrOnCmd_SBMU23_13 0 "请求正常下高压" 1 "请求上高压" 2 "强制SBMU下高压" ;
VAL_ 2148630429 HvPwrOnCmd_SBMU24_13 0 "请求正常下高压" 1 "请求上高压" 2 "强制SBMU下高压" ;
VAL_ 2148630429 HvPwrOnCmd_SBMU25_13 0 "请求正常下高压" 1 "请求上高压" 2 "强制SBMU下高压" ;
VAL_ 2148630429 HvPwrOnCmd_SBMU26_13 0 "请求正常下高压" 1 "请求上高压" 2 "强制SBMU下高压" ;
VAL_ 2148630429 HvPwrOnCmd_SBMU27_13 0 "请求正常下高压" 1 "请求上高压" 2 "强制SBMU下高压" ;
VAL_ 2148630429 HvPwrOnCmd_SBMU28_13 0 "请求正常下高压" 1 "请求上高压" 2 "强制SBMU下高压" ;
VAL_ 2148630429 HvPwrOnCmd_SBMU29_13 0 "请求正常下高压" 1 "请求上高压" 2 "强制SBMU下高压" ;
VAL_ 2148630429 HvPwrOnCmd_SBMU30_13 0 "请求正常下高压" 1 "请求上高压" 2 "强制SBMU下高压" ;
VAL_ 2148630429 HvPwrOnCmd_SBMU31_13 0 "请求正常下高压" 1 "请求上高压" 2 "强制SBMU下高压" ;
VAL_ 2148630429 HvPwrOnCmd_SBMU32_13 0 "请求正常下高压" 1 "请求上高压" 2 "强制SBMU下高压" ;
VAL_ 2148630430 HvPwrOnCmd_SBMU01_14 0 "请求正常下高压" 1 "请求上高压" 2 "强制SBMU下高压" ;
VAL_ 2148630430 HvPwrOnCmd_SBMU02_14 0 "请求正常下高压" 1 "请求上高压" 2 "强制SBMU下高压" ;
VAL_ 2148630430 HvPwrOnCmd_SBMU03_14 0 "请求正常下高压" 1 "请求上高压" 2 "强制SBMU下高压" ;
VAL_ 2148630430 HvPwrOnCmd_SBMU04_14 0 "请求正常下高压" 1 "请求上高压" 2 "强制SBMU下高压" ;
VAL_ 2148630430 HvPwrOnCmd_SBMU05_14 0 "请求正常下高压" 1 "请求上高压" 2 "强制SBMU下高压" ;
VAL_ 2148630430 HvPwrOnCmd_SBMU06_14 0 "请求正常下高压" 1 "请求上高压" 2 "强制SBMU下高压" ;
VAL_ 2148630430 HvPwrOnCmd_SBMU07_14 0 "请求正常下高压" 1 "请求上高压" 2 "强制SBMU下高压" ;
VAL_ 2148630430 HvPwrOnCmd_SBMU08_14 0 "请求正常下高压" 1 "请求上高压" 2 "强制SBMU下高压" ;
VAL_ 2148630430 HvPwrOnCmd_SBMU09_14 0 "请求正常下高压" 1 "请求上高压" 2 "强制SBMU下高压" ;
VAL_ 2148630430 HvPwrOnCmd_SBMU10_14 0 "请求正常下高压" 1 "请求上高压" 2 "强制SBMU下高压" ;
VAL_ 2148630430 HvPwrOnCmd_SBMU11_14 0 "请求正常下高压" 1 "请求上高压" 2 "强制SBMU下高压" ;
VAL_ 2148630430 HvPwrOnCmd_SBMU12_14 0 "请求正常下高压" 1 "请求上高压" 2 "强制SBMU下高压" ;
VAL_ 2148630430 HvPwrOnCmd_SBMU13_14 0 "请求正常下高压" 1 "请求上高压" 2 "强制SBMU下高压" ;
VAL_ 2148630430 HvPwrOnCmd_SBMU14_14 0 "请求正常下高压" 1 "请求上高压" 2 "强制SBMU下高压" ;
VAL_ 2148630430 HvPwrOnCmd_SBMU15_14 0 "请求正常下高压" 1 "请求上高压" 2 "强制SBMU下高压" ;
VAL_ 2148630430 HvPwrOnCmd_SBMU16_14 0 "请求正常下高压" 1 "请求上高压" 2 "强制SBMU下高压" ;
VAL_ 2148630430 HvPwrOnCmd_SBMU17_14 0 "请求正常下高压" 1 "请求上高压" 2 "强制SBMU下高压" ;
VAL_ 2148630430 HvPwrOnCmd_SBMU18_14 0 "请求正常下高压" 1 "请求上高压" 2 "强制SBMU下高压" ;
VAL_ 2148630430 HvPwrOnCmd_SBMU19_14 0 "请求正常下高压" 1 "请求上高压" 2 "强制SBMU下高压" ;
VAL_ 2148630430 HvPwrOnCmd_SBMU20_14 0 "请求正常下高压" 1 "请求上高压" 2 "强制SBMU下高压" ;
VAL_ 2148630430 HvPwrOnCmd_SBMU21_14 0 "请求正常下高压" 1 "请求上高压" 2 "强制SBMU下高压" ;
VAL_ 2148630430 HvPwrOnCmd_SBMU22_14 0 "请求正常下高压" 1 "请求上高压" 2 "强制SBMU下高压" ;
VAL_ 2148630430 HvPwrOnCmd_SBMU23_14 0 "请求正常下高压" 1 "请求上高压" 2 "强制SBMU下高压" ;
VAL_ 2148630430 HvPwrOnCmd_SBMU24_14 0 "请求正常下高压" 1 "请求上高压" 2 "强制SBMU下高压" ;
VAL_ 2148630430 HvPwrOnCmd_SBMU25_14 0 "请求正常下高压" 1 "请求上高压" 2 "强制SBMU下高压" ;
VAL_ 2148630430 HvPwrOnCmd_SBMU26_14 0 "请求正常下高压" 1 "请求上高压" 2 "强制SBMU下高压" ;
VAL_ 2148630430 HvPwrOnCmd_SBMU27_14 0 "请求正常下高压" 1 "请求上高压" 2 "强制SBMU下高压" ;
VAL_ 2148630430 HvPwrOnCmd_SBMU28_14 0 "请求正常下高压" 1 "请求上高压" 2 "强制SBMU下高压" ;
VAL_ 2148630430 HvPwrOnCmd_SBMU29_14 0 "请求正常下高压" 1 "请求上高压" 2 "强制SBMU下高压" ;
VAL_ 2148630430 HvPwrOnCmd_SBMU30_14 0 "请求正常下高压" 1 "请求上高压" 2 "强制SBMU下高压" ;
VAL_ 2148630430 HvPwrOnCmd_SBMU31_14 0 "请求正常下高压" 1 "请求上高压" 2 "强制SBMU下高压" ;
VAL_ 2148630430 HvPwrOnCmd_SBMU32_14 0 "请求正常下高压" 1 "请求上高压" 2 "强制SBMU下高压" ;
VAL_ 2148630431 HvPwrOnCmd_SBMU01_15 0 "请求正常下高压" 1 "请求上高压" 2 "强制SBMU下高压" ;
VAL_ 2148630431 HvPwrOnCmd_SBMU02_15 0 "请求正常下高压" 1 "请求上高压" 2 "强制SBMU下高压" ;
VAL_ 2148630431 HvPwrOnCmd_SBMU03_15 0 "请求正常下高压" 1 "请求上高压" 2 "强制SBMU下高压" ;
VAL_ 2148630431 HvPwrOnCmd_SBMU04_15 0 "请求正常下高压" 1 "请求上高压" 2 "强制SBMU下高压" ;
VAL_ 2148630431 HvPwrOnCmd_SBMU05_15 0 "请求正常下高压" 1 "请求上高压" 2 "强制SBMU下高压" ;
VAL_ 2148630431 HvPwrOnCmd_SBMU06_15 0 "请求正常下高压" 1 "请求上高压" 2 "强制SBMU下高压" ;
VAL_ 2148630431 HvPwrOnCmd_SBMU07_15 0 "请求正常下高压" 1 "请求上高压" 2 "强制SBMU下高压" ;
VAL_ 2148630431 HvPwrOnCmd_SBMU08_15 0 "请求正常下高压" 1 "请求上高压" 2 "强制SBMU下高压" ;
VAL_ 2148630431 HvPwrOnCmd_SBMU09_15 0 "请求正常下高压" 1 "请求上高压" 2 "强制SBMU下高压" ;
VAL_ 2148630431 HvPwrOnCmd_SBMU10_15 0 "请求正常下高压" 1 "请求上高压" 2 "强制SBMU下高压" ;
VAL_ 2148630431 HvPwrOnCmd_SBMU11_15 0 "请求正常下高压" 1 "请求上高压" 2 "强制SBMU下高压" ;
VAL_ 2148630431 HvPwrOnCmd_SBMU12_15 0 "请求正常下高压" 1 "请求上高压" 2 "强制SBMU下高压" ;
VAL_ 2148630431 HvPwrOnCmd_SBMU13_15 0 "请求正常下高压" 1 "请求上高压" 2 "强制SBMU下高压" ;
VAL_ 2148630431 HvPwrOnCmd_SBMU14_15 0 "请求正常下高压" 1 "请求上高压" 2 "强制SBMU下高压" ;
VAL_ 2148630431 HvPwrOnCmd_SBMU15_15 0 "请求正常下高压" 1 "请求上高压" 2 "强制SBMU下高压" ;
VAL_ 2148630431 HvPwrOnCmd_SBMU16_15 0 "请求正常下高压" 1 "请求上高压" 2 "强制SBMU下高压" ;
VAL_ 2148630431 HvPwrOnCmd_SBMU17_15 0 "请求正常下高压" 1 "请求上高压" 2 "强制SBMU下高压" ;
VAL_ 2148630431 HvPwrOnCmd_SBMU18_15 0 "请求正常下高压" 1 "请求上高压" 2 "强制SBMU下高压" ;
VAL_ 2148630431 HvPwrOnCmd_SBMU19_15 0 "请求正常下高压" 1 "请求上高压" 2 "强制SBMU下高压" ;
VAL_ 2148630431 HvPwrOnCmd_SBMU20_15 0 "请求正常下高压" 1 "请求上高压" 2 "强制SBMU下高压" ;
VAL_ 2148630431 HvPwrOnCmd_SBMU21_15 0 "请求正常下高压" 1 "请求上高压" 2 "强制SBMU下高压" ;
VAL_ 2148630431 HvPwrOnCmd_SBMU22_15 0 "请求正常下高压" 1 "请求上高压" 2 "强制SBMU下高压" ;
VAL_ 2148630431 HvPwrOnCmd_SBMU23_15 0 "请求正常下高压" 1 "请求上高压" 2 "强制SBMU下高压" ;
VAL_ 2148630431 HvPwrOnCmd_SBMU24_15 0 "请求正常下高压" 1 "请求上高压" 2 "强制SBMU下高压" ;
VAL_ 2148630431 HvPwrOnCmd_SBMU25_15 0 "请求正常下高压" 1 "请求上高压" 2 "强制SBMU下高压" ;
VAL_ 2148630431 HvPwrOnCmd_SBMU26_15 0 "请求正常下高压" 1 "请求上高压" 2 "强制SBMU下高压" ;
VAL_ 2148630431 HvPwrOnCmd_SBMU27_15 0 "请求正常下高压" 1 "请求上高压" 2 "强制SBMU下高压" ;
VAL_ 2148630431 HvPwrOnCmd_SBMU28_15 0 "请求正常下高压" 1 "请求上高压" 2 "强制SBMU下高压" ;
VAL_ 2148630431 HvPwrOnCmd_SBMU29_15 0 "请求正常下高压" 1 "请求上高压" 2 "强制SBMU下高压" ;
VAL_ 2148630431 HvPwrOnCmd_SBMU30_15 0 "请求正常下高压" 1 "请求上高压" 2 "强制SBMU下高压" ;
VAL_ 2148630431 HvPwrOnCmd_SBMU31_15 0 "请求正常下高压" 1 "请求上高压" 2 "强制SBMU下高压" ;
VAL_ 2148630431 HvPwrOnCmd_SBMU32_15 0 "请求正常下高压" 1 "请求上高压" 2 "强制SBMU下高压" ;
VAL_ 2148630432 HvPwrOnCmd_SBMU01_16 0 "请求正常下高压" 1 "请求上高压" 2 "强制SBMU下高压" ;
VAL_ 2148630432 HvPwrOnCmd_SBMU02_16 0 "请求正常下高压" 1 "请求上高压" 2 "强制SBMU下高压" ;
VAL_ 2148630432 HvPwrOnCmd_SBMU03_16 0 "请求正常下高压" 1 "请求上高压" 2 "强制SBMU下高压" ;
VAL_ 2148630432 HvPwrOnCmd_SBMU04_16 0 "请求正常下高压" 1 "请求上高压" 2 "强制SBMU下高压" ;
VAL_ 2148630432 HvPwrOnCmd_SBMU05_16 0 "请求正常下高压" 1 "请求上高压" 2 "强制SBMU下高压" ;
VAL_ 2148630432 HvPwrOnCmd_SBMU06_16 0 "请求正常下高压" 1 "请求上高压" 2 "强制SBMU下高压" ;
VAL_ 2148630432 HvPwrOnCmd_SBMU07_16 0 "请求正常下高压" 1 "请求上高压" 2 "强制SBMU下高压" ;
VAL_ 2148630432 HvPwrOnCmd_SBMU08_16 0 "请求正常下高压" 1 "请求上高压" 2 "强制SBMU下高压" ;
VAL_ 2148630432 HvPwrOnCmd_SBMU09_16 0 "请求正常下高压" 1 "请求上高压" 2 "强制SBMU下高压" ;
VAL_ 2148630432 HvPwrOnCmd_SBMU10_16 0 "请求正常下高压" 1 "请求上高压" 2 "强制SBMU下高压" ;
VAL_ 2148630432 HvPwrOnCmd_SBMU11_16 0 "请求正常下高压" 1 "请求上高压" 2 "强制SBMU下高压" ;
VAL_ 2148630432 HvPwrOnCmd_SBMU12_16 0 "请求正常下高压" 1 "请求上高压" 2 "强制SBMU下高压" ;
VAL_ 2148630432 HvPwrOnCmd_SBMU13_16 0 "请求正常下高压" 1 "请求上高压" 2 "强制SBMU下高压" ;
VAL_ 2148630432 HvPwrOnCmd_SBMU14_16 0 "请求正常下高压" 1 "请求上高压" 2 "强制SBMU下高压" ;
VAL_ 2148630432 HvPwrOnCmd_SBMU15_16 0 "请求正常下高压" 1 "请求上高压" 2 "强制SBMU下高压" ;
VAL_ 2148630432 HvPwrOnCmd_SBMU16_16 0 "请求正常下高压" 1 "请求上高压" 2 "强制SBMU下高压" ;
VAL_ 2148630432 HvPwrOnCmd_SBMU17_16 0 "请求正常下高压" 1 "请求上高压" 2 "强制SBMU下高压" ;
VAL_ 2148630432 HvPwrOnCmd_SBMU18_16 0 "请求正常下高压" 1 "请求上高压" 2 "强制SBMU下高压" ;
VAL_ 2148630432 HvPwrOnCmd_SBMU19_16 0 "请求正常下高压" 1 "请求上高压" 2 "强制SBMU下高压" ;
VAL_ 2148630432 HvPwrOnCmd_SBMU20_16 0 "请求正常下高压" 1 "请求上高压" 2 "强制SBMU下高压" ;
VAL_ 2148630432 HvPwrOnCmd_SBMU21_16 0 "请求正常下高压" 1 "请求上高压" 2 "强制SBMU下高压" ;
VAL_ 2148630432 HvPwrOnCmd_SBMU22_16 0 "请求正常下高压" 1 "请求上高压" 2 "强制SBMU下高压" ;
VAL_ 2148630432 HvPwrOnCmd_SBMU23_16 0 "请求正常下高压" 1 "请求上高压" 2 "强制SBMU下高压" ;
VAL_ 2148630432 HvPwrOnCmd_SBMU24_16 0 "请求正常下高压" 1 "请求上高压" 2 "强制SBMU下高压" ;
VAL_ 2148630432 HvPwrOnCmd_SBMU25_16 0 "请求正常下高压" 1 "请求上高压" 2 "强制SBMU下高压" ;
VAL_ 2148630432 HvPwrOnCmd_SBMU26_16 0 "请求正常下高压" 1 "请求上高压" 2 "强制SBMU下高压" ;
VAL_ 2148630432 HvPwrOnCmd_SBMU27_16 0 "请求正常下高压" 1 "请求上高压" 2 "强制SBMU下高压" ;
VAL_ 2148630432 HvPwrOnCmd_SBMU28_16 0 "请求正常下高压" 1 "请求上高压" 2 "强制SBMU下高压" ;
VAL_ 2148630432 HvPwrOnCmd_SBMU29_16 0 "请求正常下高压" 1 "请求上高压" 2 "强制SBMU下高压" ;
VAL_ 2148630432 HvPwrOnCmd_SBMU30_16 0 "请求正常下高压" 1 "请求上高压" 2 "强制SBMU下高压" ;
VAL_ 2148630432 HvPwrOnCmd_SBMU31_16 0 "请求正常下高压" 1 "请求上高压" 2 "强制SBMU下高压" ;
VAL_ 2148630432 HvPwrOnCmd_SBMU32_16 0 "请求正常下高压" 1 "请求上高压" 2 "强制SBMU下高压" ;
VERSION ""

NS_ :

BS_:

BU_: MBMU PC SBMU IMM ETH DCDC LEMS

BO_ 2148630433 M2S_CMD1__17: 8 MBMU
 SG_ HvPwrOnCmd_SBMU01_17 : 0|2@1+ (1,0) [0|3] ""  SBMU
 SG_ HvPwrOnCmd_SBMU02_17 : 2|2@1+ (1,0) [0|3] ""  SBMU
 SG_ HvPwrOnCmd_SBMU03_17 : 4|2@1+ (1,0) [0|3] ""  SBMU
 SG_ HvPwrOnCmd_SBMU04_17 : 6|2@1+ (1,0) [0|3] ""  SBMU
 SG_ HvPwrOnCmd_SBMU05_17 : 8|2@1+ (1,0) [0|3] ""  SBMU
 SG_ HvPwrOnCmd_SBMU06_17 : 10|2@1+ (1,0) [0|3] ""  SBMU
 SG_ HvPwrOnCmd_SBMU07_17 : 12|2@1+ (1,0) [0|3] ""  SBMU
 SG_ HvPwrOnCmd_SBMU08_17 : 14|2@1+ (1,0) [0|3] ""  SBMU
 SG_ HvPwrOnCmd_SBMU09_17 : 16|2@1+ (1,0) [0|3] ""  SBMU
 SG_ HvPwrOnCmd_SBMU10_17 : 18|2@1+ (1,0) [0|3] ""  SBMU
 SG_ HvPwrOnCmd_SBMU11_17 : 20|2@1+ (1,0) [0|3] ""  SBMU
 SG_ HvPwrOnCmd_SBMU12_17 : 22|2@1+ (1,0) [0|3] ""  SBMU
 SG_ HvPwrOnCmd_SBMU13_17 : 24|2@1+ (1,0) [0|3] ""  SBMU
 SG_ HvPwrOnCmd_SBMU14_17 : 26|2@1+ (1,0) [0|3] ""  SBMU
 SG_ HvPwrOnCmd_SBMU15_17 : 28|2@1+ (1,0) [0|3] ""  SBMU
 SG_ HvPwrOnCmd_SBMU16_17 : 30|2@1+ (1,0) [0|3] ""  SBMU
 SG_ HvPwrOnCmd_SBMU17_17 : 32|2@1+ (1,0) [0|3] ""  SBMU
 SG_ HvPwrOnCmd_SBMU18_17 : 34|2@1+ (1,0) [0|3] ""  SBMU
 SG_ HvPwrOnCmd_SBMU19_17 : 36|2@1+ (1,0) [0|3] ""  SBMU
 SG_ HvPwrOnCmd_SBMU20_17 : 38|2@1+ (1,0) [0|3] ""  SBMU
 SG_ HvPwrOnCmd_SBMU21_17 : 40|2@1+ (1,0) [0|3] ""  SBMU
 SG_ HvPwrOnCmd_SBMU22_17 : 42|2@1+ (1,0) [0|3] ""  SBMU
 SG_ HvPwrOnCmd_SBMU23_17 : 44|2@1+ (1,0) [0|3] ""  SBMU
 SG_ HvPwrOnCmd_SBMU24_17 : 46|2@1+ (1,0) [0|3] ""  SBMU
 SG_ HvPwrOnCmd_SBMU25_17 : 48|2@1+ (1,0) [0|3] ""  SBMU
 SG_ HvPwrOnCmd_SBMU26_17 : 50|2@1+ (1,0) [0|3] ""  SBMU
 SG_ HvPwrOnCmd_SBMU27_17 : 52|2@1+ (1,0) [0|3] ""  SBMU
 SG_ HvPwrOnCmd_SBMU28_17 : 54|2@1+ (1,0) [0|3] ""  SBMU
 SG_ HvPwrOnCmd_SBMU29_17 : 56|2@1+ (1,0) [0|3] ""  SBMU
 SG_ HvPwrOnCmd_SBMU30_17 : 58|2@1+ (1,0) [0|3] ""  SBMU
 SG_ HvPwrOnCmd_SBMU31_17 : 60|2@1+ (1,0) [0|3] ""  SBMU
 SG_ HvPwrOnCmd_SBMU32_17 : 62|2@1+ (1,0) [0|3] ""  SBMU

BO_ 2148630434 M2S_CMD1__18: 8 MBMU
 SG_ HvPwrOnCmd_SBMU01_18 : 0|2@1+ (1,0) [0|3] ""  SBMU
 SG_ HvPwrOnCmd_SBMU02_18 : 2|2@1+ (1,0) [0|3] ""  SBMU
 SG_ HvPwrOnCmd_SBMU03_18 : 4|2@1+ (1,0) [0|3] ""  SBMU
 SG_ HvPwrOnCmd_SBMU04_18 : 6|2@1+ (1,0) [0|3] ""  SBMU
 SG_ HvPwrOnCmd_SBMU05_18 : 8|2@1+ (1,0) [0|3] ""  SBMU
 SG_ HvPwrOnCmd_SBMU06_18 : 10|2@1+ (1,0) [0|3] ""  SBMU
 SG_ HvPwrOnCmd_SBMU07_18 : 12|2@1+ (1,0) [0|3] ""  SBMU
 SG_ HvPwrOnCmd_SBMU08_18 : 14|2@1+ (1,0) [0|3] ""  SBMU
 SG_ HvPwrOnCmd_SBMU09_18 : 16|2@1+ (1,0) [0|3] ""  SBMU
 SG_ HvPwrOnCmd_SBMU10_18 : 18|2@1+ (1,0) [0|3] ""  SBMU
 SG_ HvPwrOnCmd_SBMU11_18 : 20|2@1+ (1,0) [0|3] ""  SBMU
 SG_ HvPwrOnCmd_SBMU12_18 : 22|2@1+ (1,0) [0|3] ""  SBMU
 SG_ HvPwrOnCmd_SBMU13_18 : 24|2@1+ (1,0) [0|3] ""  SBMU
 SG_ HvPwrOnCmd_SBMU14_18 : 26|2@1+ (1,0) [0|3] ""  SBMU
 SG_ HvPwrOnCmd_SBMU15_18 : 28|2@1+ (1,0) [0|3] ""  SBMU
 SG_ HvPwrOnCmd_SBMU16_18 : 30|2@1+ (1,0) [0|3] ""  SBMU
 SG_ HvPwrOnCmd_SBMU17_18 : 32|2@1+ (1,0) [0|3] ""  SBMU
 SG_ HvPwrOnCmd_SBMU18_18 : 34|2@1+ (1,0) [0|3] ""  SBMU
 SG_ HvPwrOnCmd_SBMU19_18 : 36|2@1+ (1,0) [0|3] ""  SBMU
 SG_ HvPwrOnCmd_SBMU20_18 : 38|2@1+ (1,0) [0|3] ""  SBMU
 SG_ HvPwrOnCmd_SBMU21_18 : 40|2@1+ (1,0) [0|3] ""  SBMU
 SG_ HvPwrOnCmd_SBMU22_18 : 42|2@1+ (1,0) [0|3] ""  SBMU
 SG_ HvPwrOnCmd_SBMU23_18 : 44|2@1+ (1,0) [0|3] ""  SBMU
 SG_ HvPwrOnCmd_SBMU24_18 : 46|2@1+ (1,0) [0|3] ""  SBMU
 SG_ HvPwrOnCmd_SBMU25_18 : 48|2@1+ (1,0) [0|3] ""  SBMU
 SG_ HvPwrOnCmd_SBMU26_18 : 50|2@1+ (1,0) [0|3] ""  SBMU
 SG_ HvPwrOnCmd_SBMU27_18 : 52|2@1+ (1,0) [0|3] ""  SBMU
 SG_ HvPwrOnCmd_SBMU28_18 : 54|2@1+ (1,0) [0|3] ""  SBMU
 SG_ HvPwrOnCmd_SBMU29_18 : 56|2@1+ (1,0) [0|3] ""  SBMU
 SG_ HvPwrOnCmd_SBMU30_18 : 58|2@1+ (1,0) [0|3] ""  SBMU
 SG_ HvPwrOnCmd_SBMU31_18 : 60|2@1+ (1,0) [0|3] ""  SBMU
 SG_ HvPwrOnCmd_SBMU32_18 : 62|2@1+ (1,0) [0|3] ""  SBMU

BO_ 2148630435 M2S_CMD1__19: 8 MBMU
 SG_ HvPwrOnCmd_SBMU01_19 : 0|2@1+ (1,0) [0|3] ""  SBMU
 SG_ HvPwrOnCmd_SBMU02_19 : 2|2@1+ (1,0) [0|3] ""  SBMU
 SG_ HvPwrOnCmd_SBMU03_19 : 4|2@1+ (1,0) [0|3] ""  SBMU
 SG_ HvPwrOnCmd_SBMU04_19 : 6|2@1+ (1,0) [0|3] ""  SBMU
 SG_ HvPwrOnCmd_SBMU05_19 : 8|2@1+ (1,0) [0|3] ""  SBMU
 SG_ HvPwrOnCmd_SBMU06_19 : 10|2@1+ (1,0) [0|3] ""  SBMU
 SG_ HvPwrOnCmd_SBMU07_19 : 12|2@1+ (1,0) [0|3] ""  SBMU
 SG_ HvPwrOnCmd_SBMU08_19 : 14|2@1+ (1,0) [0|3] ""  SBMU
 SG_ HvPwrOnCmd_SBMU09_19 : 16|2@1+ (1,0) [0|3] ""  SBMU
 SG_ HvPwrOnCmd_SBMU10_19 : 18|2@1+ (1,0) [0|3] ""  SBMU
 SG_ HvPwrOnCmd_SBMU11_19 : 20|2@1+ (1,0) [0|3] ""  SBMU
 SG_ HvPwrOnCmd_SBMU12_19 : 22|2@1+ (1,0) [0|3] ""  SBMU
 SG_ HvPwrOnCmd_SBMU13_19 : 24|2@1+ (1,0) [0|3] ""  SBMU
 SG_ HvPwrOnCmd_SBMU14_19 : 26|2@1+ (1,0) [0|3] ""  SBMU
 SG_ HvPwrOnCmd_SBMU15_19 : 28|2@1+ (1,0) [0|3] ""  SBMU
 SG_ HvPwrOnCmd_SBMU16_19 : 30|2@1+ (1,0) [0|3] ""  SBMU
 SG_ HvPwrOnCmd_SBMU17_19 : 32|2@1+ (1,0) [0|3] ""  SBMU
 SG_ HvPwrOnCmd_SBMU18_19 : 34|2@1+ (1,0) [0|3] ""  SBMU
 SG_ HvPwrOnCmd_SBMU19_19 : 36|2@1+ (1,0) [0|3] ""  SBMU
 SG_ HvPwrOnCmd_SBMU20_19 : 38|2@1+ (1,0) [0|3] ""  SBMU
 SG_ HvPwrOnCmd_SBMU21_19 : 40|2@1+ (1,0) [0|3] ""  SBMU
 SG_ HvPwrOnCmd_SBMU22_19 : 42|2@1+ (1,0) [0|3] ""  SBMU
 SG_ HvPwrOnCmd_SBMU23_19 : 44|2@1+ (1,0) [0|3] ""  SBMU
 SG_ HvPwrOnCmd_SBMU24_19 : 46|2@1+ (1,0) [0|3] ""  SBMU
 SG_ HvPwrOnCmd_SBMU25_19 : 48|2@1+ (1,0) [0|3] ""  SBMU
 SG_ HvPwrOnCmd_SBMU26_19 : 50|2@1+ (1,0) [0|3] ""  SBMU
 SG_ HvPwrOnCmd_SBMU27_19 : 52|2@1+ (1,0) [0|3] ""  SBMU
 SG_ HvPwrOnCmd_SBMU28_19 : 54|2@1+ (1,0) [0|3] ""  SBMU
 SG_ HvPwrOnCmd_SBMU29_19 : 56|2@1+ (1,0) [0|3] ""  SBMU
 SG_ HvPwrOnCmd_SBMU30_19 : 58|2@1+ (1,0) [0|3] ""  SBMU
 SG_ HvPwrOnCmd_SBMU31_19 : 60|2@1+ (1,0) [0|3] ""  SBMU
 SG_ HvPwrOnCmd_SBMU32_19 : 62|2@1+ (1,0) [0|3] ""  SBMU

BO_ 2148630436 M2S_CMD1__20: 8 MBMU
 SG_ HvPwrOnCmd_SBMU01_20 : 0|2@1+ (1,0) [0|3] ""  SBMU
 SG_ HvPwrOnCmd_SBMU02_20 : 2|2@1+ (1,0) [0|3] ""  SBMU
 SG_ HvPwrOnCmd_SBMU03_20 : 4|2@1+ (1,0) [0|3] ""  SBMU
 SG_ HvPwrOnCmd_SBMU04_20 : 6|2@1+ (1,0) [0|3] ""  SBMU
 SG_ HvPwrOnCmd_SBMU05_20 : 8|2@1+ (1,0) [0|3] ""  SBMU
 SG_ HvPwrOnCmd_SBMU06_20 : 10|2@1+ (1,0) [0|3] ""  SBMU
 SG_ HvPwrOnCmd_SBMU07_20 : 12|2@1+ (1,0) [0|3] ""  SBMU
 SG_ HvPwrOnCmd_SBMU08_20 : 14|2@1+ (1,0) [0|3] ""  SBMU
 SG_ HvPwrOnCmd_SBMU09_20 : 16|2@1+ (1,0) [0|3] ""  SBMU
 SG_ HvPwrOnCmd_SBMU10_20 : 18|2@1+ (1,0) [0|3] ""  SBMU
 SG_ HvPwrOnCmd_SBMU11_20 : 20|2@1+ (1,0) [0|3] ""  SBMU
 SG_ HvPwrOnCmd_SBMU12_20 : 22|2@1+ (1,0) [0|3] ""  SBMU
 SG_ HvPwrOnCmd_SBMU13_20 : 24|2@1+ (1,0) [0|3] ""  SBMU
 SG_ HvPwrOnCmd_SBMU14_20 : 26|2@1+ (1,0) [0|3] ""  SBMU
 SG_ HvPwrOnCmd_SBMU15_20 : 28|2@1+ (1,0) [0|3] ""  SBMU
 SG_ HvPwrOnCmd_SBMU16_20 : 30|2@1+ (1,0) [0|3] ""  SBMU
 SG_ HvPwrOnCmd_SBMU17_20 : 32|2@1+ (1,0) [0|3] ""  SBMU
 SG_ HvPwrOnCmd_SBMU18_20 : 34|2@1+ (1,0) [0|3] ""  SBMU
 SG_ HvPwrOnCmd_SBMU19_20 : 36|2@1+ (1,0) [0|3] ""  SBMU
 SG_ HvPwrOnCmd_SBMU20_20 : 38|2@1+ (1,0) [0|3] ""  SBMU
 SG_ HvPwrOnCmd_SBMU21_20 : 40|2@1+ (1,0) [0|3] ""  SBMU
 SG_ HvPwrOnCmd_SBMU22_20 : 42|2@1+ (1,0) [0|3] ""  SBMU
 SG_ HvPwrOnCmd_SBMU23_20 : 44|2@1+ (1,0) [0|3] ""  SBMU
 SG_ HvPwrOnCmd_SBMU24_20 : 46|2@1+ (1,0) [0|3] ""  SBMU
 SG_ HvPwrOnCmd_SBMU25_20 : 48|2@1+ (1,0) [0|3] ""  SBMU
 SG_ HvPwrOnCmd_SBMU26_20 : 50|2@1+ (1,0) [0|3] ""  SBMU
 SG_ HvPwrOnCmd_SBMU27_20 : 52|2@1+ (1,0) [0|3] ""  SBMU
 SG_ HvPwrOnCmd_SBMU28_20 : 54|2@1+ (1,0) [0|3] ""  SBMU
 SG_ HvPwrOnCmd_SBMU29_20 : 56|2@1+ (1,0) [0|3] ""  SBMU
 SG_ HvPwrOnCmd_SBMU30_20 : 58|2@1+ (1,0) [0|3] ""  SBMU
 SG_ HvPwrOnCmd_SBMU31_20 : 60|2@1+ (1,0) [0|3] ""  SBMU
 SG_ HvPwrOnCmd_SBMU32_20 : 62|2@1+ (1,0) [0|3] ""  SBMU

BO_ 2148630437 M2S_CMD1__21: 8 MBMU
 SG_ HvPwrOnCmd_SBMU01_21 : 0|2@1+ (1,0) [0|3] ""  SBMU
 SG_ HvPwrOnCmd_SBMU02_21 : 2|2@1+ (1,0) [0|3] ""  SBMU
 SG_ HvPwrOnCmd_SBMU03_21 : 4|2@1+ (1,0) [0|3] ""  SBMU
 SG_ HvPwrOnCmd_SBMU04_21 : 6|2@1+ (1,0) [0|3] ""  SBMU
 SG_ HvPwrOnCmd_SBMU05_21 : 8|2@1+ (1,0) [0|3] ""  SBMU
 SG_ HvPwrOnCmd_SBMU06_21 : 10|2@1+ (1,0) [0|3] ""  SBMU
 SG_ HvPwrOnCmd_SBMU07_21 : 12|2@1+ (1,0) [0|3] ""  SBMU
 SG_ HvPwrOnCmd_SBMU08_21 : 14|2@1+ (1,0) [0|3] ""  SBMU
 SG_ HvPwrOnCmd_SBMU09_21 : 16|2@1+ (1,0) [0|3] ""  SBMU
 SG_ HvPwrOnCmd_SBMU10_21 : 18|2@1+ (1,0) [0|3] ""  SBMU
 SG_ HvPwrOnCmd_SBMU11_21 : 20|2@1+ (1,0) [0|3] ""  SBMU
 SG_ HvPwrOnCmd_SBMU12_21 : 22|2@1+ (1,0) [0|3] ""  SBMU
 SG_ HvPwrOnCmd_SBMU13_21 : 24|2@1+ (1,0) [0|3] ""  SBMU
 SG_ HvPwrOnCmd_SBMU14_21 : 26|2@1+ (1,0) [0|3] ""  SBMU
 SG_ HvPwrOnCmd_SBMU15_21 : 28|2@1+ (1,0) [0|3] ""  SBMU
 SG_ HvPwrOnCmd_SBMU16_21 : 30|2@1+ (1,0) [0|3] ""  SBMU
 SG_ HvPwrOnCmd_SBMU17_21 : 32|2@1+ (1,0) [0|3] ""  SBMU
 SG_ HvPwrOnCmd_SBMU18_21 : 34|2@1+ (1,0) [0|3] ""  SBMU
 SG_ HvPwrOnCmd_SBMU19_21 : 36|2@1+ (1,0) [0|3] ""  SBMU
 SG_ HvPwrOnCmd_SBMU20_21 : 38|2@1+ (1,0) [0|3] ""  SBMU
 SG_ HvPwrOnCmd_SBMU21_21 : 40|2@1+ (1,0) [0|3] ""  SBMU
 SG_ HvPwrOnCmd_SBMU22_21 : 42|2@1+ (1,0) [0|3] ""  SBMU
 SG_ HvPwrOnCmd_SBMU23_21 : 44|2@1+ (1,0) [0|3] ""  SBMU
 SG_ HvPwrOnCmd_SBMU24_21 : 46|2@1+ (1,0) [0|3] ""  SBMU
 SG_ HvPwrOnCmd_SBMU25_21 : 48|2@1+ (1,0) [0|3] ""  SBMU
 SG_ HvPwrOnCmd_SBMU26_21 : 50|2@1+ (1,0) [0|3] ""  SBMU
 SG_ HvPwrOnCmd_SBMU27_21 : 52|2@1+ (1,0) [0|3] ""  SBMU
 SG_ HvPwrOnCmd_SBMU28_21 : 54|2@1+ (1,0) [0|3] ""  SBMU
 SG_ HvPwrOnCmd_SBMU29_21 : 56|2@1+ (1,0) [0|3] ""  SBMU
 SG_ HvPwrOnCmd_SBMU30_21 : 58|2@1+ (1,0) [0|3] ""  SBMU
 SG_ HvPwrOnCmd_SBMU31_21 : 60|2@1+ (1,0) [0|3] ""  SBMU
 SG_ HvPwrOnCmd_SBMU32_21 : 62|2@1+ (1,0) [0|3] ""  SBMU

BO_ 2148630438 M2S_CMD1__22: 8 MBMU
 SG_ HvPwrOnCmd_SBMU01_22 : 0|2@1+ (1,0) [0|3] ""  SBMU
 SG_ HvPwrOnCmd_SBMU02_22 : 2|2@1+ (1,0) [0|3] ""  SBMU
 SG_ HvPwrOnCmd_SBMU03_22 : 4|2@1+ (1,0) [0|3] ""  SBMU
 SG_ HvPwrOnCmd_SBMU04_22 : 6|2@1+ (1,0) [0|3] ""  SBMU
 SG_ HvPwrOnCmd_SBMU05_22 : 8|2@1+ (1,0) [0|3] ""  SBMU
 SG_ HvPwrOnCmd_SBMU06_22 : 10|2@1+ (1,0) [0|3] ""  SBMU
 SG_ HvPwrOnCmd_SBMU07_22 : 12|2@1+ (1,0) [0|3] ""  SBMU
 SG_ HvPwrOnCmd_SBMU08_22 : 14|2@1+ (1,0) [0|3] ""  SBMU
 SG_ HvPwrOnCmd_SBMU09_22 : 16|2@1+ (1,0) [0|3] ""  SBMU
 SG_ HvPwrOnCmd_SBMU10_22 : 18|2@1+ (1,0) [0|3] ""  SBMU
 SG_ HvPwrOnCmd_SBMU11_22 : 20|2@1+ (1,0) [0|3] ""  SBMU
 SG_ HvPwrOnCmd_SBMU12_22 : 22|2@1+ (1,0) [0|3] ""  SBMU
 SG_ HvPwrOnCmd_SBMU13_22 : 24|2@1+ (1,0) [0|3] ""  SBMU
 SG_ HvPwrOnCmd_SBMU14_22 : 26|2@1+ (1,0) [0|3] ""  SBMU
 SG_ HvPwrOnCmd_SBMU15_22 : 28|2@1+ (1,0) [0|3] ""  SBMU
 SG_ HvPwrOnCmd_SBMU16_22 : 30|2@1+ (1,0) [0|3] ""  SBMU
 SG_ HvPwrOnCmd_SBMU17_22 : 32|2@1+ (1,0) [0|3] ""  SBMU
 SG_ HvPwrOnCmd_SBMU18_22 : 34|2@1+ (1,0) [0|3] ""  SBMU
 SG_ HvPwrOnCmd_SBMU19_22 : 36|2@1+ (1,0) [0|3] ""  SBMU
 SG_ HvPwrOnCmd_SBMU20_22 : 38|2@1+ (1,0) [0|3] ""  SBMU
 SG_ HvPwrOnCmd_SBMU21_22 : 40|2@1+ (1,0) [0|3] ""  SBMU
 SG_ HvPwrOnCmd_SBMU22_22 : 42|2@1+ (1,0) [0|3] ""  SBMU
 SG_ HvPwrOnCmd_SBMU23_22 : 44|2@1+ (1,0) [0|3] ""  SBMU
 SG_ HvPwrOnCmd_SBMU24_22 : 46|2@1+ (1,0) [0|3] ""  SBMU
 SG_ HvPwrOnCmd_SBMU25_22 : 48|2@1+ (1,0) [0|3] ""  SBMU
 SG_ HvPwrOnCmd_SBMU26_22 : 50|2@1+ (1,0) [0|3] ""  SBMU
 SG_ HvPwrOnCmd_SBMU27_22 : 52|2@1+ (1,0) [0|3] ""  SBMU
 SG_ HvPwrOnCmd_SBMU28_22 : 54|2@1+ (1,0) [0|3] ""  SBMU
 SG_ HvPwrOnCmd_SBMU29_22 : 56|2@1+ (1,0) [0|3] ""  SBMU
 SG_ HvPwrOnCmd_SBMU30_22 : 58|2@1+ (1,0) [0|3] ""  SBMU
 SG_ HvPwrOnCmd_SBMU31_22 : 60|2@1+ (1,0) [0|3] ""  SBMU
 SG_ HvPwrOnCmd_SBMU32_22 : 62|2@1+ (1,0) [0|3] ""  SBMU

BO_ 2148630439 M2S_CMD1__23: 8 MBMU
 SG_ HvPwrOnCmd_SBMU01_23 : 0|2@1+ (1,0) [0|3] ""  SBMU
 SG_ HvPwrOnCmd_SBMU02_23 : 2|2@1+ (1,0) [0|3] ""  SBMU
 SG_ HvPwrOnCmd_SBMU03_23 : 4|2@1+ (1,0) [0|3] ""  SBMU
 SG_ HvPwrOnCmd_SBMU04_23 : 6|2@1+ (1,0) [0|3] ""  SBMU
 SG_ HvPwrOnCmd_SBMU05_23 : 8|2@1+ (1,0) [0|3] ""  SBMU
 SG_ HvPwrOnCmd_SBMU06_23 : 10|2@1+ (1,0) [0|3] ""  SBMU
 SG_ HvPwrOnCmd_SBMU07_23 : 12|2@1+ (1,0) [0|3] ""  SBMU
 SG_ HvPwrOnCmd_SBMU08_23 : 14|2@1+ (1,0) [0|3] ""  SBMU
 SG_ HvPwrOnCmd_SBMU09_23 : 16|2@1+ (1,0) [0|3] ""  SBMU
 SG_ HvPwrOnCmd_SBMU10_23 : 18|2@1+ (1,0) [0|3] ""  SBMU
 SG_ HvPwrOnCmd_SBMU11_23 : 20|2@1+ (1,0) [0|3] ""  SBMU
 SG_ HvPwrOnCmd_SBMU12_23 : 22|2@1+ (1,0) [0|3] ""  SBMU
 SG_ HvPwrOnCmd_SBMU13_23 : 24|2@1+ (1,0) [0|3] ""  SBMU
 SG_ HvPwrOnCmd_SBMU14_23 : 26|2@1+ (1,0) [0|3] ""  SBMU
 SG_ HvPwrOnCmd_SBMU15_23 : 28|2@1+ (1,0) [0|3] ""  SBMU
 SG_ HvPwrOnCmd_SBMU16_23 : 30|2@1+ (1,0) [0|3] ""  SBMU
 SG_ HvPwrOnCmd_SBMU17_23 : 32|2@1+ (1,0) [0|3] ""  SBMU
 SG_ HvPwrOnCmd_SBMU18_23 : 34|2@1+ (1,0) [0|3] ""  SBMU
 SG_ HvPwrOnCmd_SBMU19_23 : 36|2@1+ (1,0) [0|3] ""  SBMU
 SG_ HvPwrOnCmd_SBMU20_23 : 38|2@1+ (1,0) [0|3] ""  SBMU
 SG_ HvPwrOnCmd_SBMU21_23 : 40|2@1+ (1,0) [0|3] ""  SBMU
 SG_ HvPwrOnCmd_SBMU22_23 : 42|2@1+ (1,0) [0|3] ""  SBMU
 SG_ HvPwrOnCmd_SBMU23_23 : 44|2@1+ (1,0) [0|3] ""  SBMU
 SG_ HvPwrOnCmd_SBMU24_23 : 46|2@1+ (1,0) [0|3] ""  SBMU
 SG_ HvPwrOnCmd_SBMU25_23 : 48|2@1+ (1,0) [0|3] ""  SBMU
 SG_ HvPwrOnCmd_SBMU26_23 : 50|2@1+ (1,0) [0|3] ""  SBMU
 SG_ HvPwrOnCmd_SBMU27_23 : 52|2@1+ (1,0) [0|3] ""  SBMU
 SG_ HvPwrOnCmd_SBMU28_23 : 54|2@1+ (1,0) [0|3] ""  SBMU
 SG_ HvPwrOnCmd_SBMU29_23 : 56|2@1+ (1,0) [0|3] ""  SBMU
 SG_ HvPwrOnCmd_SBMU30_23 : 58|2@1+ (1,0) [0|3] ""  SBMU
 SG_ HvPwrOnCmd_SBMU31_23 : 60|2@1+ (1,0) [0|3] ""  SBMU
 SG_ HvPwrOnCmd_SBMU32_23 : 62|2@1+ (1,0) [0|3] ""  SBMU

BO_ 2148630440 M2S_CMD1__24: 8 MBMU
 SG_ HvPwrOnCmd_SBMU01_24 : 0|2@1+ (1,0) [0|3] ""  SBMU
 SG_ HvPwrOnCmd_SBMU02_24 : 2|2@1+ (1,0) [0|3] ""  SBMU
 SG_ HvPwrOnCmd_SBMU03_24 : 4|2@1+ (1,0) [0|3] ""  SBMU
 SG_ HvPwrOnCmd_SBMU04_24 : 6|2@1+ (1,0) [0|3] ""  SBMU
 SG_ HvPwrOnCmd_SBMU05_24 : 8|2@1+ (1,0) [0|3] ""  SBMU
 SG_ HvPwrOnCmd_SBMU06_24 : 10|2@1+ (1,0) [0|3] ""  SBMU
 SG_ HvPwrOnCmd_SBMU07_24 : 12|2@1+ (1,0) [0|3] ""  SBMU
 SG_ HvPwrOnCmd_SBMU08_24 : 14|2@1+ (1,0) [0|3] ""  SBMU
 SG_ HvPwrOnCmd_SBMU09_24 : 16|2@1+ (1,0) [0|3] ""  SBMU
 SG_ HvPwrOnCmd_SBMU10_24 : 18|2@1+ (1,0) [0|3] ""  SBMU
 SG_ HvPwrOnCmd_SBMU11_24 : 20|2@1+ (1,0) [0|3] ""  SBMU
 SG_ HvPwrOnCmd_SBMU12_24 : 22|2@1+ (1,0) [0|3] ""  SBMU
 SG_ HvPwrOnCmd_SBMU13_24 : 24|2@1+ (1,0) [0|3] ""  SBMU
 SG_ HvPwrOnCmd_SBMU14_24 : 26|2@1+ (1,0) [0|3] ""  SBMU
 SG_ HvPwrOnCmd_SBMU15_24 : 28|2@1+ (1,0) [0|3] ""  SBMU
 SG_ HvPwrOnCmd_SBMU16_24 : 30|2@1+ (1,0) [0|3] ""  SBMU
 SG_ HvPwrOnCmd_SBMU17_24 : 32|2@1+ (1,0) [0|3] ""  SBMU
 SG_ HvPwrOnCmd_SBMU18_24 : 34|2@1+ (1,0) [0|3] ""  SBMU
 SG_ HvPwrOnCmd_SBMU19_24 : 36|2@1+ (1,0) [0|3] ""  SBMU
 SG_ HvPwrOnCmd_SBMU20_24 : 38|2@1+ (1,0) [0|3] ""  SBMU
 SG_ HvPwrOnCmd_SBMU21_24 : 40|2@1+ (1,0) [0|3] ""  SBMU
 SG_ HvPwrOnCmd_SBMU22_24 : 42|2@1+ (1,0) [0|3] ""  SBMU
 SG_ HvPwrOnCmd_SBMU23_24 : 44|2@1+ (1,0) [0|3] ""  SBMU
 SG_ HvPwrOnCmd_SBMU24_24 : 46|2@1+ (1,0) [0|3] ""  SBMU
 SG_ HvPwrOnCmd_SBMU25_24 : 48|2@1+ (1,0) [0|3] ""  SBMU
 SG_ HvPwrOnCmd_SBMU26_24 : 50|2@1+ (1,0) [0|3] ""  SBMU
 SG_ HvPwrOnCmd_SBMU27_24 : 52|2@1+ (1,0) [0|3] ""  SBMU
 SG_ HvPwrOnCmd_SBMU28_24 : 54|2@1+ (1,0) [0|3] ""  SBMU
 SG_ HvPwrOnCmd_SBMU29_24 : 56|2@1+ (1,0) [0|3] ""  SBMU
 SG_ HvPwrOnCmd_SBMU30_24 : 58|2@1+ (1,0) [0|3] ""  SBMU
 SG_ HvPwrOnCmd_SBMU31_24 : 60|2@1+ (1,0) [0|3] ""  SBMU
 SG_ HvPwrOnCmd_SBMU32_24 : 62|2@1+ (1,0) [0|3] ""  SBMU

BO_ 2148630441 M2S_CMD1__25: 8 MBMU
 SG_ HvPwrOnCmd_SBMU01_25 : 0|2@1+ (1,0) [0|3] ""  SBMU
 SG_ HvPwrOnCmd_SBMU02_25 : 2|2@1+ (1,0) [0|3] ""  SBMU
 SG_ HvPwrOnCmd_SBMU03_25 : 4|2@1+ (1,0) [0|3] ""  SBMU
 SG_ HvPwrOnCmd_SBMU04_25 : 6|2@1+ (1,0) [0|3] ""  SBMU
 SG_ HvPwrOnCmd_SBMU05_25 : 8|2@1+ (1,0) [0|3] ""  SBMU
 SG_ HvPwrOnCmd_SBMU06_25 : 10|2@1+ (1,0) [0|3] ""  SBMU
 SG_ HvPwrOnCmd_SBMU07_25 : 12|2@1+ (1,0) [0|3] ""  SBMU
 SG_ HvPwrOnCmd_SBMU08_25 : 14|2@1+ (1,0) [0|3] ""  SBMU
 SG_ HvPwrOnCmd_SBMU09_25 : 16|2@1+ (1,0) [0|3] ""  SBMU
 SG_ HvPwrOnCmd_SBMU10_25 : 18|2@1+ (1,0) [0|3] ""  SBMU
 SG_ HvPwrOnCmd_SBMU11_25 : 20|2@1+ (1,0) [0|3] ""  SBMU
 SG_ HvPwrOnCmd_SBMU12_25 : 22|2@1+ (1,0) [0|3] ""  SBMU
 SG_ HvPwrOnCmd_SBMU13_25 : 24|2@1+ (1,0) [0|3] ""  SBMU
 SG_ HvPwrOnCmd_SBMU14_25 : 26|2@1+ (1,0) [0|3] ""  SBMU
 SG_ HvPwrOnCmd_SBMU15_25 : 28|2@1+ (1,0) [0|3] ""  SBMU
 SG_ HvPwrOnCmd_SBMU16_25 : 30|2@1+ (1,0) [0|3] ""  SBMU
 SG_ HvPwrOnCmd_SBMU17_25 : 32|2@1+ (1,0) [0|3] ""  SBMU
 SG_ HvPwrOnCmd_SBMU18_25 : 34|2@1+ (1,0) [0|3] ""  SBMU
 SG_ HvPwrOnCmd_SBMU19_25 : 36|2@1+ (1,0) [0|3] ""  SBMU
 SG_ HvPwrOnCmd_SBMU20_25 : 38|2@1+ (1,0) [0|3] ""  SBMU
 SG_ HvPwrOnCmd_SBMU21_25 : 40|2@1+ (1,0) [0|3] ""  SBMU
 SG_ HvPwrOnCmd_SBMU22_25 : 42|2@1+ (1,0) [0|3] ""  SBMU
 SG_ HvPwrOnCmd_SBMU23_25 : 44|2@1+ (1,0) [0|3] ""  SBMU
 SG_ HvPwrOnCmd_SBMU24_25 : 46|2@1+ (1,0) [0|3] ""  SBMU
 SG_ HvPwrOnCmd_SBMU25_25 : 48|2@1+ (1,0) [0|3] ""  SBMU
 SG_ HvPwrOnCmd_SBMU26_25 : 50|2@1+ (1,0) [0|3] ""  SBMU
 SG_ HvPwrOnCmd_SBMU27_25 : 52|2@1+ (1,0) [0|3] ""  SBMU
 SG_ HvPwrOnCmd_SBMU28_25 : 54|2@1+ (1,0) [0|3] ""  SBMU
 SG_ HvPwrOnCmd_SBMU29_25 : 56|2@1+ (1,0) [0|3] ""  SBMU
 SG_ HvPwrOnCmd_SBMU30_25 : 58|2@1+ (1,0) [0|3] ""  SBMU
 SG_ HvPwrOnCmd_SBMU31_25 : 60|2@1+ (1,0) [0|3] ""  SBMU
 SG_ HvPwrOnCmd_SBMU32_25 : 62|2@1+ (1,0) [0|3] ""  SBMU

BO_ 2148630442 M2S_CMD1__26: 8 MBMU
 SG_ HvPwrOnCmd_SBMU01_26 : 0|2@1+ (1,0) [0|3] ""  SBMU
 SG_ HvPwrOnCmd_SBMU02_26 : 2|2@1+ (1,0) [0|3] ""  SBMU
 SG_ HvPwrOnCmd_SBMU03_26 : 4|2@1+ (1,0) [0|3] ""  SBMU
 SG_ HvPwrOnCmd_SBMU04_26 : 6|2@1+ (1,0) [0|3] ""  SBMU
 SG_ HvPwrOnCmd_SBMU05_26 : 8|2@1+ (1,0) [0|3] ""  SBMU
 SG_ HvPwrOnCmd_SBMU06_26 : 10|2@1+ (1,0) [0|3] ""  SBMU
 SG_ HvPwrOnCmd_SBMU07_26 : 12|2@1+ (1,0) [0|3] ""  SBMU
 SG_ HvPwrOnCmd_SBMU08_26 : 14|2@1+ (1,0) [0|3] ""  SBMU
 SG_ HvPwrOnCmd_SBMU09_26 : 16|2@1+ (1,0) [0|3] ""  SBMU
 SG_ HvPwrOnCmd_SBMU10_26 : 18|2@1+ (1,0) [0|3] ""  SBMU
 SG_ HvPwrOnCmd_SBMU11_26 : 20|2@1+ (1,0) [0|3] ""  SBMU
 SG_ HvPwrOnCmd_SBMU12_26 : 22|2@1+ (1,0) [0|3] ""  SBMU
 SG_ HvPwrOnCmd_SBMU13_26 : 24|2@1+ (1,0) [0|3] ""  SBMU
 SG_ HvPwrOnCmd_SBMU14_26 : 26|2@1+ (1,0) [0|3] ""  SBMU
 SG_ HvPwrOnCmd_SBMU15_26 : 28|2@1+ (1,0) [0|3] ""  SBMU
 SG_ HvPwrOnCmd_SBMU16_26 : 30|2@1+ (1,0) [0|3] ""  SBMU
 SG_ HvPwrOnCmd_SBMU17_26 : 32|2@1+ (1,0) [0|3] ""  SBMU
 SG_ HvPwrOnCmd_SBMU18_26 : 34|2@1+ (1,0) [0|3] ""  SBMU
 SG_ HvPwrOnCmd_SBMU19_26 : 36|2@1+ (1,0) [0|3] ""  SBMU
 SG_ HvPwrOnCmd_SBMU20_26 : 38|2@1+ (1,0) [0|3] ""  SBMU
 SG_ HvPwrOnCmd_SBMU21_26 : 40|2@1+ (1,0) [0|3] ""  SBMU
 SG_ HvPwrOnCmd_SBMU22_26 : 42|2@1+ (1,0) [0|3] ""  SBMU
 SG_ HvPwrOnCmd_SBMU23_26 : 44|2@1+ (1,0) [0|3] ""  SBMU
 SG_ HvPwrOnCmd_SBMU24_26 : 46|2@1+ (1,0) [0|3] ""  SBMU
 SG_ HvPwrOnCmd_SBMU25_26 : 48|2@1+ (1,0) [0|3] ""  SBMU
 SG_ HvPwrOnCmd_SBMU26_26 : 50|2@1+ (1,0) [0|3] ""  SBMU
 SG_ HvPwrOnCmd_SBMU27_26 : 52|2@1+ (1,0) [0|3] ""  SBMU
 SG_ HvPwrOnCmd_SBMU28_26 : 54|2@1+ (1,0) [0|3] ""  SBMU
 SG_ HvPwrOnCmd_SBMU29_26 : 56|2@1+ (1,0) [0|3] ""  SBMU
 SG_ HvPwrOnCmd_SBMU30_26 : 58|2@1+ (1,0) [0|3] ""  SBMU
 SG_ HvPwrOnCmd_SBMU31_26 : 60|2@1+ (1,0) [0|3] ""  SBMU
 SG_ HvPwrOnCmd_SBMU32_26 : 62|2@1+ (1,0) [0|3] ""  SBMU

BO_ 2148630443 M2S_CMD1__27: 8 MBMU
 SG_ HvPwrOnCmd_SBMU01_27 : 0|2@1+ (1,0) [0|3] ""  SBMU
 SG_ HvPwrOnCmd_SBMU02_27 : 2|2@1+ (1,0) [0|3] ""  SBMU
 SG_ HvPwrOnCmd_SBMU03_27 : 4|2@1+ (1,0) [0|3] ""  SBMU
 SG_ HvPwrOnCmd_SBMU04_27 : 6|2@1+ (1,0) [0|3] ""  SBMU
 SG_ HvPwrOnCmd_SBMU05_27 : 8|2@1+ (1,0) [0|3] ""  SBMU
 SG_ HvPwrOnCmd_SBMU06_27 : 10|2@1+ (1,0) [0|3] ""  SBMU
 SG_ HvPwrOnCmd_SBMU07_27 : 12|2@1+ (1,0) [0|3] ""  SBMU
 SG_ HvPwrOnCmd_SBMU08_27 : 14|2@1+ (1,0) [0|3] ""  SBMU
 SG_ HvPwrOnCmd_SBMU09_27 : 16|2@1+ (1,0) [0|3] ""  SBMU
 SG_ HvPwrOnCmd_SBMU10_27 : 18|2@1+ (1,0) [0|3] ""  SBMU
 SG_ HvPwrOnCmd_SBMU11_27 : 20|2@1+ (1,0) [0|3] ""  SBMU
 SG_ HvPwrOnCmd_SBMU12_27 : 22|2@1+ (1,0) [0|3] ""  SBMU
 SG_ HvPwrOnCmd_SBMU13_27 : 24|2@1+ (1,0) [0|3] ""  SBMU
 SG_ HvPwrOnCmd_SBMU14_27 : 26|2@1+ (1,0) [0|3] ""  SBMU
 SG_ HvPwrOnCmd_SBMU15_27 : 28|2@1+ (1,0) [0|3] ""  SBMU
 SG_ HvPwrOnCmd_SBMU16_27 : 30|2@1+ (1,0) [0|3] ""  SBMU
 SG_ HvPwrOnCmd_SBMU17_27 : 32|2@1+ (1,0) [0|3] ""  SBMU
 SG_ HvPwrOnCmd_SBMU18_27 : 34|2@1+ (1,0) [0|3] ""  SBMU
 SG_ HvPwrOnCmd_SBMU19_27 : 36|2@1+ (1,0) [0|3] ""  SBMU
 SG_ HvPwrOnCmd_SBMU20_27 : 38|2@1+ (1,0) [0|3] ""  SBMU
 SG_ HvPwrOnCmd_SBMU21_27 : 40|2@1+ (1,0) [0|3] ""  SBMU
 SG_ HvPwrOnCmd_SBMU22_27 : 42|2@1+ (1,0) [0|3] ""  SBMU
 SG_ HvPwrOnCmd_SBMU23_27 : 44|2@1+ (1,0) [0|3] ""  SBMU
 SG_ HvPwrOnCmd_SBMU24_27 : 46|2@1+ (1,0) [0|3] ""  SBMU
 SG_ HvPwrOnCmd_SBMU25_27 : 48|2@1+ (1,0) [0|3] ""  SBMU
 SG_ HvPwrOnCmd_SBMU26_27 : 50|2@1+ (1,0) [0|3] ""  SBMU
 SG_ HvPwrOnCmd_SBMU27_27 : 52|2@1+ (1,0) [0|3] ""  SBMU
 SG_ HvPwrOnCmd_SBMU28_27 : 54|2@1+ (1,0) [0|3] ""  SBMU
 SG_ HvPwrOnCmd_SBMU29_27 : 56|2@1+ (1,0) [0|3] ""  SBMU
 SG_ HvPwrOnCmd_SBMU30_27 : 58|2@1+ (1,0) [0|3] ""  SBMU
 SG_ HvPwrOnCmd_SBMU31_27 : 60|2@1+ (1,0) [0|3] ""  SBMU
 SG_ HvPwrOnCmd_SBMU32_27 : 62|2@1+ (1,0) [0|3] ""  SBMU

BO_ 2148630444 M2S_CMD1__28: 8 MBMU
 SG_ HvPwrOnCmd_SBMU01_28 : 0|2@1+ (1,0) [0|3] ""  SBMU
 SG_ HvPwrOnCmd_SBMU02_28 : 2|2@1+ (1,0) [0|3] ""  SBMU
 SG_ HvPwrOnCmd_SBMU03_28 : 4|2@1+ (1,0) [0|3] ""  SBMU
 SG_ HvPwrOnCmd_SBMU04_28 : 6|2@1+ (1,0) [0|3] ""  SBMU
 SG_ HvPwrOnCmd_SBMU05_28 : 8|2@1+ (1,0) [0|3] ""  SBMU
 SG_ HvPwrOnCmd_SBMU06_28 : 10|2@1+ (1,0) [0|3] ""  SBMU
 SG_ HvPwrOnCmd_SBMU07_28 : 12|2@1+ (1,0) [0|3] ""  SBMU
 SG_ HvPwrOnCmd_SBMU08_28 : 14|2@1+ (1,0) [0|3] ""  SBMU
 SG_ HvPwrOnCmd_SBMU09_28 : 16|2@1+ (1,0) [0|3] ""  SBMU
 SG_ HvPwrOnCmd_SBMU10_28 : 18|2@1+ (1,0) [0|3] ""  SBMU
 SG_ HvPwrOnCmd_SBMU11_28 : 20|2@1+ (1,0) [0|3] ""  SBMU
 SG_ HvPwrOnCmd_SBMU12_28 : 22|2@1+ (1,0) [0|3] ""  SBMU
 SG_ HvPwrOnCmd_SBMU13_28 : 24|2@1+ (1,0) [0|3] ""  SBMU
 SG_ HvPwrOnCmd_SBMU14_28 : 26|2@1+ (1,0) [0|3] ""  SBMU
 SG_ HvPwrOnCmd_SBMU15_28 : 28|2@1+ (1,0) [0|3] ""  SBMU
 SG_ HvPwrOnCmd_SBMU16_28 : 30|2@1+ (1,0) [0|3] ""  SBMU
 SG_ HvPwrOnCmd_SBMU17_28 : 32|2@1+ (1,0) [0|3] ""  SBMU
 SG_ HvPwrOnCmd_SBMU18_28 : 34|2@1+ (1,0) [0|3] ""  SBMU
 SG_ HvPwrOnCmd_SBMU19_28 : 36|2@1+ (1,0) [0|3] ""  SBMU
 SG_ HvPwrOnCmd_SBMU20_28 : 38|2@1+ (1,0) [0|3] ""  SBMU
 SG_ HvPwrOnCmd_SBMU21_28 : 40|2@1+ (1,0) [0|3] ""  SBMU
 SG_ HvPwrOnCmd_SBMU22_28 : 42|2@1+ (1,0) [0|3] ""  SBMU
 SG_ HvPwrOnCmd_SBMU23_28 : 44|2@1+ (1,0) [0|3] ""  SBMU
 SG_ HvPwrOnCmd_SBMU24_28 : 46|2@1+ (1,0) [0|3] ""  SBMU
 SG_ HvPwrOnCmd_SBMU25_28 : 48|2@1+ (1,0) [0|3] ""  SBMU
 SG_ HvPwrOnCmd_SBMU26_28 : 50|2@1+ (1,0) [0|3] ""  SBMU
 SG_ HvPwrOnCmd_SBMU27_28 : 52|2@1+ (1,0) [0|3] ""  SBMU
 SG_ HvPwrOnCmd_SBMU28_28 : 54|2@1+ (1,0) [0|3] ""  SBMU
 SG_ HvPwrOnCmd_SBMU29_28 : 56|2@1+ (1,0) [0|3] ""  SBMU
 SG_ HvPwrOnCmd_SBMU30_28 : 58|2@1+ (1,0) [0|3] ""  SBMU
 SG_ HvPwrOnCmd_SBMU31_28 : 60|2@1+ (1,0) [0|3] ""  SBMU
 SG_ HvPwrOnCmd_SBMU32_28 : 62|2@1+ (1,0) [0|3] ""  SBMU

BO_ 2148630445 M2S_CMD1__29: 8 MBMU
 SG_ HvPwrOnCmd_SBMU01_29 : 0|2@1+ (1,0) [0|3] ""  SBMU
 SG_ HvPwrOnCmd_SBMU02_29 : 2|2@1+ (1,0) [0|3] ""  SBMU
 SG_ HvPwrOnCmd_SBMU03_29 : 4|2@1+ (1,0) [0|3] ""  SBMU
 SG_ HvPwrOnCmd_SBMU04_29 : 6|2@1+ (1,0) [0|3] ""  SBMU
 SG_ HvPwrOnCmd_SBMU05_29 : 8|2@1+ (1,0) [0|3] ""  SBMU
 SG_ HvPwrOnCmd_SBMU06_29 : 10|2@1+ (1,0) [0|3] ""  SBMU
 SG_ HvPwrOnCmd_SBMU07_29 : 12|2@1+ (1,0) [0|3] ""  SBMU
 SG_ HvPwrOnCmd_SBMU08_29 : 14|2@1+ (1,0) [0|3] ""  SBMU
 SG_ HvPwrOnCmd_SBMU09_29 : 16|2@1+ (1,0) [0|3] ""  SBMU
 SG_ HvPwrOnCmd_SBMU10_29 : 18|2@1+ (1,0) [0|3] ""  SBMU
 SG_ HvPwrOnCmd_SBMU11_29 : 20|2@1+ (1,0) [0|3] ""  SBMU
 SG_ HvPwrOnCmd_SBMU12_29 : 22|2@1+ (1,0) [0|3] ""  SBMU
 SG_ HvPwrOnCmd_SBMU13_29 : 24|2@1+ (1,0) [0|3] ""  SBMU
 SG_ HvPwrOnCmd_SBMU14_29 : 26|2@1+ (1,0) [0|3] ""  SBMU
 SG_ HvPwrOnCmd_SBMU15_29 : 28|2@1+ (1,0) [0|3] ""  SBMU
 SG_ HvPwrOnCmd_SBMU16_29 : 30|2@1+ (1,0) [0|3] ""  SBMU
 SG_ HvPwrOnCmd_SBMU17_29 : 32|2@1+ (1,0) [0|3] ""  SBMU
 SG_ HvPwrOnCmd_SBMU18_29 : 34|2@1+ (1,0) [0|3] ""  SBMU
 SG_ HvPwrOnCmd_SBMU19_29 : 36|2@1+ (1,0) [0|3] ""  SBMU
 SG_ HvPwrOnCmd_SBMU20_29 : 38|2@1+ (1,0) [0|3] ""  SBMU
 SG_ HvPwrOnCmd_SBMU21_29 : 40|2@1+ (1,0) [0|3] ""  SBMU
 SG_ HvPwrOnCmd_SBMU22_29 : 42|2@1+ (1,0) [0|3] ""  SBMU
 SG_ HvPwrOnCmd_SBMU23_29 : 44|2@1+ (1,0) [0|3] ""  SBMU
 SG_ HvPwrOnCmd_SBMU24_29 : 46|2@1+ (1,0) [0|3] ""  SBMU
 SG_ HvPwrOnCmd_SBMU25_29 : 48|2@1+ (1,0) [0|3] ""  SBMU
 SG_ HvPwrOnCmd_SBMU26_29 : 50|2@1+ (1,0) [0|3] ""  SBMU
 SG_ HvPwrOnCmd_SBMU27_29 : 52|2@1+ (1,0) [0|3] ""  SBMU
 SG_ HvPwrOnCmd_SBMU28_29 : 54|2@1+ (1,0) [0|3] ""  SBMU
 SG_ HvPwrOnCmd_SBMU29_29 : 56|2@1+ (1,0) [0|3] ""  SBMU
 SG_ HvPwrOnCmd_SBMU30_29 : 58|2@1+ (1,0) [0|3] ""  SBMU
 SG_ HvPwrOnCmd_SBMU31_29 : 60|2@1+ (1,0) [0|3] ""  SBMU
 SG_ HvPwrOnCmd_SBMU32_29 : 62|2@1+ (1,0) [0|3] ""  SBMU

BO_ 2148630446 M2S_CMD1__30: 8 MBMU
 SG_ HvPwrOnCmd_SBMU01_30 : 0|2@1+ (1,0) [0|3] ""  SBMU
 SG_ HvPwrOnCmd_SBMU02_30 : 2|2@1+ (1,0) [0|3] ""  SBMU
 SG_ HvPwrOnCmd_SBMU03_30 : 4|2@1+ (1,0) [0|3] ""  SBMU
 SG_ HvPwrOnCmd_SBMU04_30 : 6|2@1+ (1,0) [0|3] ""  SBMU
 SG_ HvPwrOnCmd_SBMU05_30 : 8|2@1+ (1,0) [0|3] ""  SBMU
 SG_ HvPwrOnCmd_SBMU06_30 : 10|2@1+ (1,0) [0|3] ""  SBMU
 SG_ HvPwrOnCmd_SBMU07_30 : 12|2@1+ (1,0) [0|3] ""  SBMU
 SG_ HvPwrOnCmd_SBMU08_30 : 14|2@1+ (1,0) [0|3] ""  SBMU
 SG_ HvPwrOnCmd_SBMU09_30 : 16|2@1+ (1,0) [0|3] ""  SBMU
 SG_ HvPwrOnCmd_SBMU10_30 : 18|2@1+ (1,0) [0|3] ""  SBMU
 SG_ HvPwrOnCmd_SBMU11_30 : 20|2@1+ (1,0) [0|3] ""  SBMU
 SG_ HvPwrOnCmd_SBMU12_30 : 22|2@1+ (1,0) [0|3] ""  SBMU
 SG_ HvPwrOnCmd_SBMU13_30 : 24|2@1+ (1,0) [0|3] ""  SBMU
 SG_ HvPwrOnCmd_SBMU14_30 : 26|2@1+ (1,0) [0|3] ""  SBMU
 SG_ HvPwrOnCmd_SBMU15_30 : 28|2@1+ (1,0) [0|3] ""  SBMU
 SG_ HvPwrOnCmd_SBMU16_30 : 30|2@1+ (1,0) [0|3] ""  SBMU
 SG_ HvPwrOnCmd_SBMU17_30 : 32|2@1+ (1,0) [0|3] ""  SBMU
 SG_ HvPwrOnCmd_SBMU18_30 : 34|2@1+ (1,0) [0|3] ""  SBMU
 SG_ HvPwrOnCmd_SBMU19_30 : 36|2@1+ (1,0) [0|3] ""  SBMU
 SG_ HvPwrOnCmd_SBMU20_30 : 38|2@1+ (1,0) [0|3] ""  SBMU
 SG_ HvPwrOnCmd_SBMU21_30 : 40|2@1+ (1,0) [0|3] ""  SBMU
 SG_ HvPwrOnCmd_SBMU22_30 : 42|2@1+ (1,0) [0|3] ""  SBMU
 SG_ HvPwrOnCmd_SBMU23_30 : 44|2@1+ (1,0) [0|3] ""  SBMU
 SG_ HvPwrOnCmd_SBMU24_30 : 46|2@1+ (1,0) [0|3] ""  SBMU
 SG_ HvPwrOnCmd_SBMU25_30 : 48|2@1+ (1,0) [0|3] ""  SBMU
 SG_ HvPwrOnCmd_SBMU26_30 : 50|2@1+ (1,0) [0|3] ""  SBMU
 SG_ HvPwrOnCmd_SBMU27_30 : 52|2@1+ (1,0) [0|3] ""  SBMU
 SG_ HvPwrOnCmd_SBMU28_30 : 54|2@1+ (1,0) [0|3] ""  SBMU
 SG_ HvPwrOnCmd_SBMU29_30 : 56|2@1+ (1,0) [0|3] ""  SBMU
 SG_ HvPwrOnCmd_SBMU30_30 : 58|2@1+ (1,0) [0|3] ""  SBMU
 SG_ HvPwrOnCmd_SBMU31_30 : 60|2@1+ (1,0) [0|3] ""  SBMU
 SG_ HvPwrOnCmd_SBMU32_30 : 62|2@1+ (1,0) [0|3] ""  SBMU

BO_ 2148630447 M2S_CMD1__31: 8 MBMU
 SG_ HvPwrOnCmd_SBMU01_31 : 0|2@1+ (1,0) [0|3] ""  SBMU
 SG_ HvPwrOnCmd_SBMU02_31 : 2|2@1+ (1,0) [0|3] ""  SBMU
 SG_ HvPwrOnCmd_SBMU03_31 : 4|2@1+ (1,0) [0|3] ""  SBMU
 SG_ HvPwrOnCmd_SBMU04_31 : 6|2@1+ (1,0) [0|3] ""  SBMU
 SG_ HvPwrOnCmd_SBMU05_31 : 8|2@1+ (1,0) [0|3] ""  SBMU
 SG_ HvPwrOnCmd_SBMU06_31 : 10|2@1+ (1,0) [0|3] ""  SBMU
 SG_ HvPwrOnCmd_SBMU07_31 : 12|2@1+ (1,0) [0|3] ""  SBMU
 SG_ HvPwrOnCmd_SBMU08_31 : 14|2@1+ (1,0) [0|3] ""  SBMU
 SG_ HvPwrOnCmd_SBMU09_31 : 16|2@1+ (1,0) [0|3] ""  SBMU
 SG_ HvPwrOnCmd_SBMU10_31 : 18|2@1+ (1,0) [0|3] ""  SBMU
 SG_ HvPwrOnCmd_SBMU11_31 : 20|2@1+ (1,0) [0|3] ""  SBMU
 SG_ HvPwrOnCmd_SBMU12_31 : 22|2@1+ (1,0) [0|3] ""  SBMU
 SG_ HvPwrOnCmd_SBMU13_31 : 24|2@1+ (1,0) [0|3] ""  SBMU
 SG_ HvPwrOnCmd_SBMU14_31 : 26|2@1+ (1,0) [0|3] ""  SBMU
 SG_ HvPwrOnCmd_SBMU15_31 : 28|2@1+ (1,0) [0|3] ""  SBMU
 SG_ HvPwrOnCmd_SBMU16_31 : 30|2@1+ (1,0) [0|3] ""  SBMU
 SG_ HvPwrOnCmd_SBMU17_31 : 32|2@1+ (1,0) [0|3] ""  SBMU
 SG_ HvPwrOnCmd_SBMU18_31 : 34|2@1+ (1,0) [0|3] ""  SBMU
 SG_ HvPwrOnCmd_SBMU19_31 : 36|2@1+ (1,0) [0|3] ""  SBMU
 SG_ HvPwrOnCmd_SBMU20_31 : 38|2@1+ (1,0) [0|3] ""  SBMU
 SG_ HvPwrOnCmd_SBMU21_31 : 40|2@1+ (1,0) [0|3] ""  SBMU
 SG_ HvPwrOnCmd_SBMU22_31 : 42|2@1+ (1,0) [0|3] ""  SBMU
 SG_ HvPwrOnCmd_SBMU23_31 : 44|2@1+ (1,0) [0|3] ""  SBMU
 SG_ HvPwrOnCmd_SBMU24_31 : 46|2@1+ (1,0) [0|3] ""  SBMU
 SG_ HvPwrOnCmd_SBMU25_31 : 48|2@1+ (1,0) [0|3] ""  SBMU
 SG_ HvPwrOnCmd_SBMU26_31 : 50|2@1+ (1,0) [0|3] ""  SBMU
 SG_ HvPwrOnCmd_SBMU27_31 : 52|2@1+ (1,0) [0|3] ""  SBMU
 SG_ HvPwrOnCmd_SBMU28_31 : 54|2@1+ (1,0) [0|3] ""  SBMU
 SG_ HvPwrOnCmd_SBMU29_31 : 56|2@1+ (1,0) [0|3] ""  SBMU
 SG_ HvPwrOnCmd_SBMU30_31 : 58|2@1+ (1,0) [0|3] ""  SBMU
 SG_ HvPwrOnCmd_SBMU31_31 : 60|2@1+ (1,0) [0|3] ""  SBMU
 SG_ HvPwrOnCmd_SBMU32_31 : 62|2@1+ (1,0) [0|3] ""  SBMU

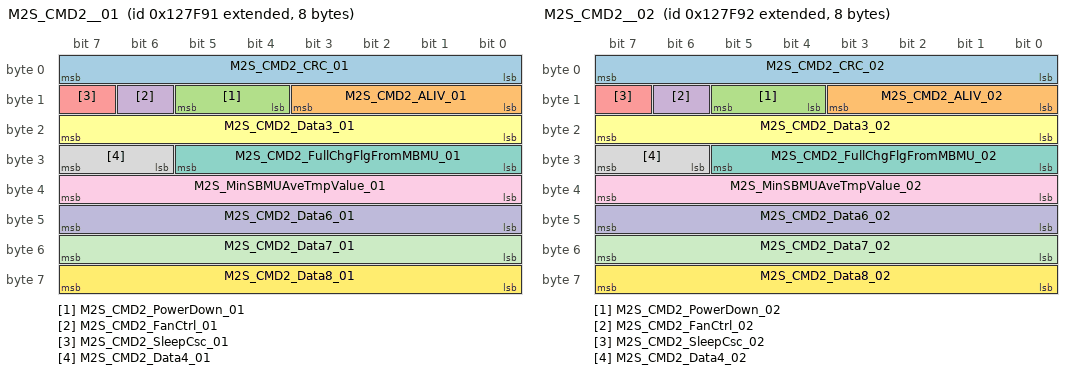
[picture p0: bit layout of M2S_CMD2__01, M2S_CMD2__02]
BO_ 2148695953 M2S_CMD2__01: 8 MBMU
 SG_ M2S_CMD2_CRC_01 : 0|8@1+ (1,0) [0|255] ""  SBMU
 SG_ M2S_CMD2_ALIV_01 : 8|4@1+ (1,0) [0|15] ""  SBMU
 SG_ M2S_CMD2_PowerDown_01 : 12|2@1+ (1,0) [0|3] ""  SBMU
 SG_ M2S_CMD2_FanCtrl_01 : 14|1@1+ (1,0) [0|1] ""  SBMU
 SG_ M2S_CMD2_SleepCsc_01 : 15|1@1+ (1,0) [0|1] ""  SBMU
 SG_ M2S_CMD2_Data3_01 : 16|8@1+ (1,0) [0|255] ""  SBMU
 SG_ M2S_CMD2_FullChgFlgFromMBMU_01 : 24|6@1+ (1,0) [0|63] ""  SBMU
 SG_ M2S_CMD2_Data4_01 : 30|2@1+ (1,0) [0|3] ""  SBMU
 SG_ M2S_MinSBMUAveTmpValue_01 : 32|8@1+ (1,-50) [-50|205] ""  SBMU
 SG_ M2S_CMD2_Data6_01 : 40|8@1+ (1,0) [0|255] ""  SBMU
 SG_ M2S_CMD2_Data7_01 : 48|8@1+ (1,0) [0|255] ""  SBMU
 SG_ M2S_CMD2_Data8_01 : 56|8@1+ (1,0) [0|255] ""  SBMU

BO_ 2148695954 M2S_CMD2__02: 8 MBMU
 SG_ M2S_CMD2_CRC_02 : 0|8@1+ (1,0) [0|255] ""  SBMU
 SG_ M2S_CMD2_ALIV_02 : 8|4@1+ (1,0) [0|15] ""  SBMU
 SG_ M2S_CMD2_PowerDown_02 : 12|2@1+ (1,0) [0|3] ""  SBMU
 SG_ M2S_CMD2_FanCtrl_02 : 14|1@1+ (1,0) [0|1] ""  SBMU
 SG_ M2S_CMD2_SleepCsc_02 : 15|1@1+ (1,0) [0|1] ""  SBMU
 SG_ M2S_CMD2_Data3_02 : 16|8@1+ (1,0) [0|255] ""  SBMU
 SG_ M2S_CMD2_FullChgFlgFromMBMU_02 : 24|6@1+ (1,0) [0|63] ""  SBMU
 SG_ M2S_CMD2_Data4_02 : 30|2@1+ (1,0) [0|3] ""  SBMU
 SG_ M2S_MinSBMUAveTmpValue_02 : 32|8@1+ (1,-50) [-50|205] ""  SBMU
 SG_ M2S_CMD2_Data6_02 : 40|8@1+ (1,0) [0|255] ""  SBMU
 SG_ M2S_CMD2_Data7_02 : 48|8@1+ (1,0) [0|255] ""  SBMU
 SG_ M2S_CMD2_Data8_02 : 56|8@1+ (1,0) [0|255] ""  SBMU

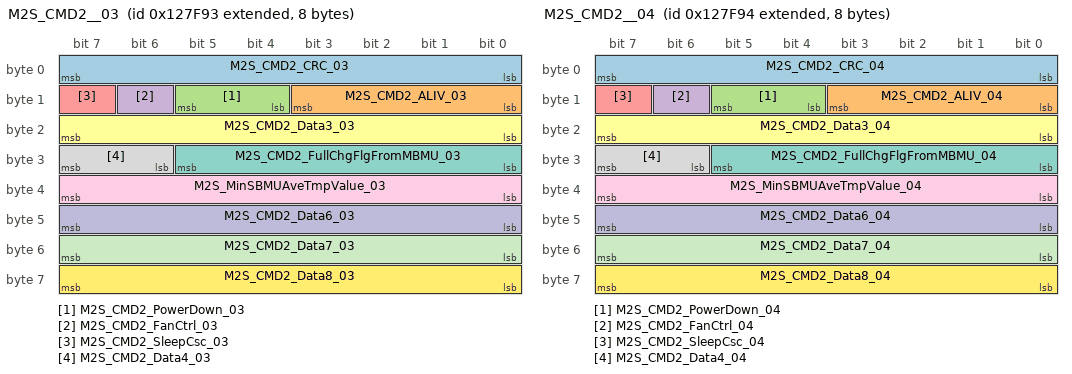
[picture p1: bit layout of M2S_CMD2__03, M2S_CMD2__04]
BO_ 2148695955 M2S_CMD2__03: 8 MBMU
 SG_ M2S_CMD2_CRC_03 : 0|8@1+ (1,0) [0|255] ""  SBMU
 SG_ M2S_CMD2_ALIV_03 : 8|4@1+ (1,0) [0|15] ""  SBMU
 SG_ M2S_CMD2_PowerDown_03 : 12|2@1+ (1,0) [0|3] ""  SBMU
 SG_ M2S_CMD2_FanCtrl_03 : 14|1@1+ (1,0) [0|1] ""  SBMU
 SG_ M2S_CMD2_SleepCsc_03 : 15|1@1+ (1,0) [0|1] ""  SBMU
 SG_ M2S_CMD2_Data3_03 : 16|8@1+ (1,0) [0|255] ""  SBMU
 SG_ M2S_CMD2_FullChgFlgFromMBMU_03 : 24|6@1+ (1,0) [0|63] ""  SBMU
 SG_ M2S_CMD2_Data4_03 : 30|2@1+ (1,0) [0|3] ""  SBMU
 SG_ M2S_MinSBMUAveTmpValue_03 : 32|8@1+ (1,-50) [-50|205] ""  SBMU
 SG_ M2S_CMD2_Data6_03 : 40|8@1+ (1,0) [0|255] ""  SBMU
 SG_ M2S_CMD2_Data7_03 : 48|8@1+ (1,0) [0|255] ""  SBMU
 SG_ M2S_CMD2_Data8_03 : 56|8@1+ (1,0) [0|255] ""  SBMU

BO_ 2148695956 M2S_CMD2__04: 8 MBMU
 SG_ M2S_CMD2_CRC_04 : 0|8@1+ (1,0) [0|255] ""  SBMU
 SG_ M2S_CMD2_ALIV_04 : 8|4@1+ (1,0) [0|15] ""  SBMU
 SG_ M2S_CMD2_PowerDown_04 : 12|2@1+ (1,0) [0|3] ""  SBMU
 SG_ M2S_CMD2_FanCtrl_04 : 14|1@1+ (1,0) [0|1] ""  SBMU
 SG_ M2S_CMD2_SleepCsc_04 : 15|1@1+ (1,0) [0|1] ""  SBMU
 SG_ M2S_CMD2_Data3_04 : 16|8@1+ (1,0) [0|255] ""  SBMU
 SG_ M2S_CMD2_FullChgFlgFromMBMU_04 : 24|6@1+ (1,0) [0|63] ""  SBMU
 SG_ M2S_CMD2_Data4_04 : 30|2@1+ (1,0) [0|3] ""  SBMU
 SG_ M2S_MinSBMUAveTmpValue_04 : 32|8@1+ (1,-50) [-50|205] ""  SBMU
 SG_ M2S_CMD2_Data6_04 : 40|8@1+ (1,0) [0|255] ""  SBMU
 SG_ M2S_CMD2_Data7_04 : 48|8@1+ (1,0) [0|255] ""  SBMU
 SG_ M2S_CMD2_Data8_04 : 56|8@1+ (1,0) [0|255] ""  SBMU

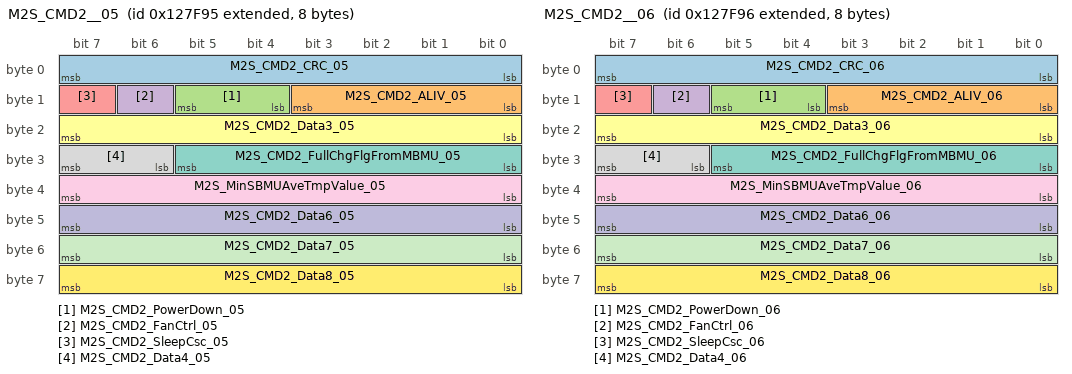
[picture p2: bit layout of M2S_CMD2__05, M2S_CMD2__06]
BO_ 2148695957 M2S_CMD2__05: 8 MBMU
 SG_ M2S_CMD2_CRC_05 : 0|8@1+ (1,0) [0|255] ""  SBMU
 SG_ M2S_CMD2_ALIV_05 : 8|4@1+ (1,0) [0|15] ""  SBMU
 SG_ M2S_CMD2_PowerDown_05 : 12|2@1+ (1,0) [0|3] ""  SBMU
 SG_ M2S_CMD2_FanCtrl_05 : 14|1@1+ (1,0) [0|1] ""  SBMU
 SG_ M2S_CMD2_SleepCsc_05 : 15|1@1+ (1,0) [0|1] ""  SBMU
 SG_ M2S_CMD2_Data3_05 : 16|8@1+ (1,0) [0|255] ""  SBMU
 SG_ M2S_CMD2_FullChgFlgFromMBMU_05 : 24|6@1+ (1,0) [0|63] ""  SBMU
 SG_ M2S_CMD2_Data4_05 : 30|2@1+ (1,0) [0|3] ""  SBMU
 SG_ M2S_MinSBMUAveTmpValue_05 : 32|8@1+ (1,-50) [-50|205] ""  SBMU
 SG_ M2S_CMD2_Data6_05 : 40|8@1+ (1,0) [0|255] ""  SBMU
 SG_ M2S_CMD2_Data7_05 : 48|8@1+ (1,0) [0|255] ""  SBMU
 SG_ M2S_CMD2_Data8_05 : 56|8@1+ (1,0) [0|255] ""  SBMU

BO_ 2148695958 M2S_CMD2__06: 8 MBMU
 SG_ M2S_CMD2_CRC_06 : 0|8@1+ (1,0) [0|255] ""  SBMU
 SG_ M2S_CMD2_ALIV_06 : 8|4@1+ (1,0) [0|15] ""  SBMU
 SG_ M2S_CMD2_PowerDown_06 : 12|2@1+ (1,0) [0|3] ""  SBMU
 SG_ M2S_CMD2_FanCtrl_06 : 14|1@1+ (1,0) [0|1] ""  SBMU
 SG_ M2S_CMD2_SleepCsc_06 : 15|1@1+ (1,0) [0|1] ""  SBMU
 SG_ M2S_CMD2_Data3_06 : 16|8@1+ (1,0) [0|255] ""  SBMU
 SG_ M2S_CMD2_FullChgFlgFromMBMU_06 : 24|6@1+ (1,0) [0|63] ""  SBMU
 SG_ M2S_CMD2_Data4_06 : 30|2@1+ (1,0) [0|3] ""  SBMU
 SG_ M2S_MinSBMUAveTmpValue_06 : 32|8@1+ (1,-50) [-50|205] ""  SBMU
 SG_ M2S_CMD2_Data6_06 : 40|8@1+ (1,0) [0|255] ""  SBMU
 SG_ M2S_CMD2_Data7_06 : 48|8@1+ (1,0) [0|255] ""  SBMU
 SG_ M2S_CMD2_Data8_06 : 56|8@1+ (1,0) [0|255] ""  SBMU

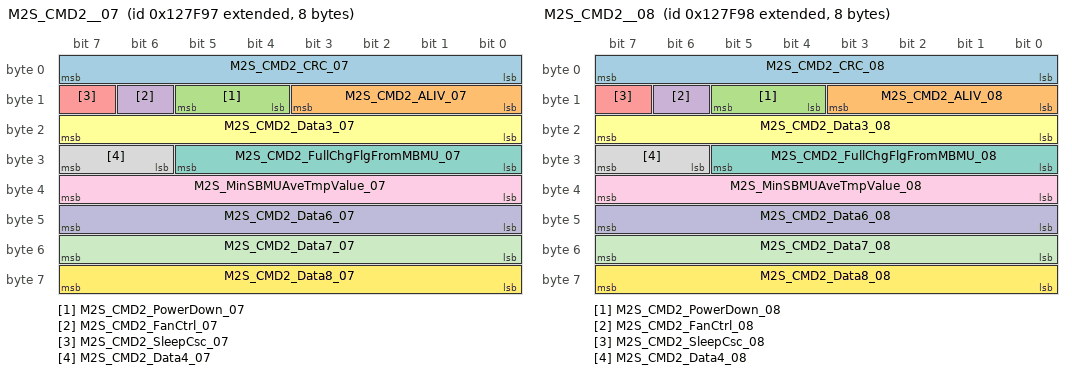
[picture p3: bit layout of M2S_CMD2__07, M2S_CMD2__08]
BO_ 2148695959 M2S_CMD2__07: 8 MBMU
 SG_ M2S_CMD2_CRC_07 : 0|8@1+ (1,0) [0|255] ""  SBMU
 SG_ M2S_CMD2_ALIV_07 : 8|4@1+ (1,0) [0|15] ""  SBMU
 SG_ M2S_CMD2_PowerDown_07 : 12|2@1+ (1,0) [0|3] ""  SBMU
 SG_ M2S_CMD2_FanCtrl_07 : 14|1@1+ (1,0) [0|1] ""  SBMU
 SG_ M2S_CMD2_SleepCsc_07 : 15|1@1+ (1,0) [0|1] ""  SBMU
 SG_ M2S_CMD2_Data3_07 : 16|8@1+ (1,0) [0|255] ""  SBMU
 SG_ M2S_CMD2_FullChgFlgFromMBMU_07 : 24|6@1+ (1,0) [0|63] ""  SBMU
 SG_ M2S_CMD2_Data4_07 : 30|2@1+ (1,0) [0|3] ""  SBMU
 SG_ M2S_MinSBMUAveTmpValue_07 : 32|8@1+ (1,-50) [-50|205] ""  SBMU
 SG_ M2S_CMD2_Data6_07 : 40|8@1+ (1,0) [0|255] ""  SBMU
 SG_ M2S_CMD2_Data7_07 : 48|8@1+ (1,0) [0|255] ""  SBMU
 SG_ M2S_CMD2_Data8_07 : 56|8@1+ (1,0) [0|255] ""  SBMU

BO_ 2148695960 M2S_CMD2__08: 8 MBMU
 SG_ M2S_CMD2_CRC_08 : 0|8@1+ (1,0) [0|255] ""  SBMU
 SG_ M2S_CMD2_ALIV_08 : 8|4@1+ (1,0) [0|15] ""  SBMU
 SG_ M2S_CMD2_PowerDown_08 : 12|2@1+ (1,0) [0|3] ""  SBMU
 SG_ M2S_CMD2_FanCtrl_08 : 14|1@1+ (1,0) [0|1] ""  SBMU
 SG_ M2S_CMD2_SleepCsc_08 : 15|1@1+ (1,0) [0|1] ""  SBMU
 SG_ M2S_CMD2_Data3_08 : 16|8@1+ (1,0) [0|255] ""  SBMU
 SG_ M2S_CMD2_FullChgFlgFromMBMU_08 : 24|6@1+ (1,0) [0|63] ""  SBMU
 SG_ M2S_CMD2_Data4_08 : 30|2@1+ (1,0) [0|3] ""  SBMU
 SG_ M2S_MinSBMUAveTmpValue_08 : 32|8@1+ (1,-50) [-50|205] ""  SBMU
 SG_ M2S_CMD2_Data6_08 : 40|8@1+ (1,0) [0|255] ""  SBMU
 SG_ M2S_CMD2_Data7_08 : 48|8@1+ (1,0) [0|255] ""  SBMU
 SG_ M2S_CMD2_Data8_08 : 56|8@1+ (1,0) [0|255] ""  SBMU

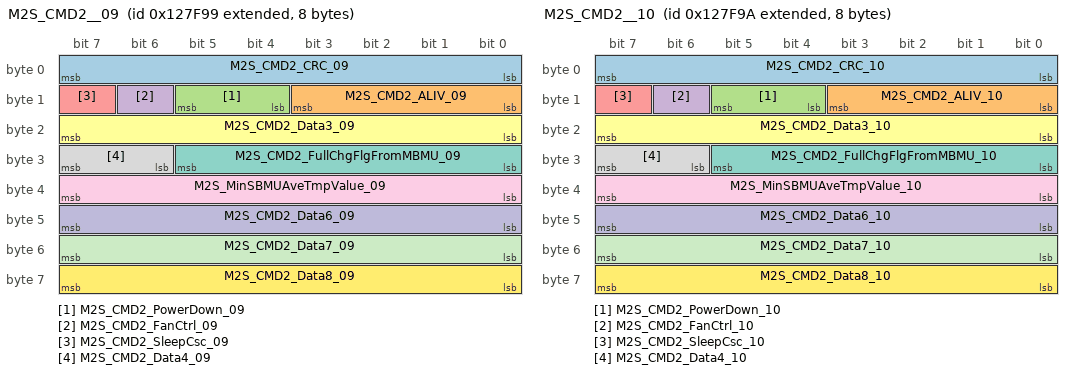
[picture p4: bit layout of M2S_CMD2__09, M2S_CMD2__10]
BO_ 2148695961 M2S_CMD2__09: 8 MBMU
 SG_ M2S_CMD2_CRC_09 : 0|8@1+ (1,0) [0|255] ""  SBMU
 SG_ M2S_CMD2_ALIV_09 : 8|4@1+ (1,0) [0|15] ""  SBMU
 SG_ M2S_CMD2_PowerDown_09 : 12|2@1+ (1,0) [0|3] ""  SBMU
 SG_ M2S_CMD2_FanCtrl_09 : 14|1@1+ (1,0) [0|1] ""  SBMU
 SG_ M2S_CMD2_SleepCsc_09 : 15|1@1+ (1,0) [0|1] ""  SBMU
 SG_ M2S_CMD2_Data3_09 : 16|8@1+ (1,0) [0|255] ""  SBMU
 SG_ M2S_CMD2_FullChgFlgFromMBMU_09 : 24|6@1+ (1,0) [0|63] ""  SBMU
 SG_ M2S_CMD2_Data4_09 : 30|2@1+ (1,0) [0|3] ""  SBMU
 SG_ M2S_MinSBMUAveTmpValue_09 : 32|8@1+ (1,-50) [-50|205] ""  SBMU
 SG_ M2S_CMD2_Data6_09 : 40|8@1+ (1,0) [0|255] ""  SBMU
 SG_ M2S_CMD2_Data7_09 : 48|8@1+ (1,0) [0|255] ""  SBMU
 SG_ M2S_CMD2_Data8_09 : 56|8@1+ (1,0) [0|255] ""  SBMU

BO_ 2148695962 M2S_CMD2__10: 8 MBMU
 SG_ M2S_CMD2_CRC_10 : 0|8@1+ (1,0) [0|255] ""  SBMU
 SG_ M2S_CMD2_ALIV_10 : 8|4@1+ (1,0) [0|15] ""  SBMU
 SG_ M2S_CMD2_PowerDown_10 : 12|2@1+ (1,0) [0|3] ""  SBMU
 SG_ M2S_CMD2_FanCtrl_10 : 14|1@1+ (1,0) [0|1] ""  SBMU
 SG_ M2S_CMD2_SleepCsc_10 : 15|1@1+ (1,0) [0|1] ""  SBMU
 SG_ M2S_CMD2_Data3_10 : 16|8@1+ (1,0) [0|255] ""  SBMU
 SG_ M2S_CMD2_FullChgFlgFromMBMU_10 : 24|6@1+ (1,0) [0|63] ""  SBMU
 SG_ M2S_CMD2_Data4_10 : 30|2@1+ (1,0) [0|3] ""  SBMU
 SG_ M2S_MinSBMUAveTmpValue_10 : 32|8@1+ (1,-50) [-50|205] ""  SBMU
 SG_ M2S_CMD2_Data6_10 : 40|8@1+ (1,0) [0|255] ""  SBMU
 SG_ M2S_CMD2_Data7_10 : 48|8@1+ (1,0) [0|255] ""  SBMU
 SG_ M2S_CMD2_Data8_10 : 56|8@1+ (1,0) [0|255] ""  SBMU

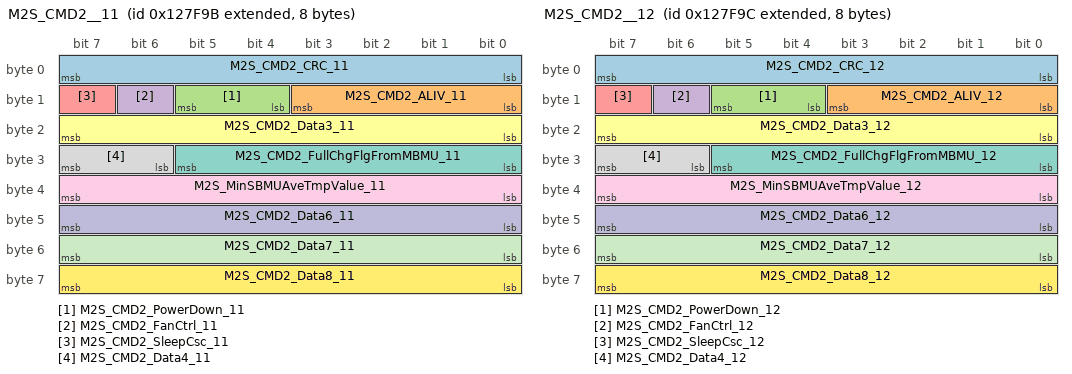
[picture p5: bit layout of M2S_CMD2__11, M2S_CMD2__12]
BO_ 2148695963 M2S_CMD2__11: 8 MBMU
 SG_ M2S_CMD2_CRC_11 : 0|8@1+ (1,0) [0|255] ""  SBMU
 SG_ M2S_CMD2_ALIV_11 : 8|4@1+ (1,0) [0|15] ""  SBMU
 SG_ M2S_CMD2_PowerDown_11 : 12|2@1+ (1,0) [0|3] ""  SBMU
 SG_ M2S_CMD2_FanCtrl_11 : 14|1@1+ (1,0) [0|1] ""  SBMU
 SG_ M2S_CMD2_SleepCsc_11 : 15|1@1+ (1,0) [0|1] ""  SBMU
 SG_ M2S_CMD2_Data3_11 : 16|8@1+ (1,0) [0|255] ""  SBMU
 SG_ M2S_CMD2_FullChgFlgFromMBMU_11 : 24|6@1+ (1,0) [0|63] ""  SBMU
 SG_ M2S_CMD2_Data4_11 : 30|2@1+ (1,0) [0|3] ""  SBMU
 SG_ M2S_MinSBMUAveTmpValue_11 : 32|8@1+ (1,-50) [-50|205] ""  SBMU
 SG_ M2S_CMD2_Data6_11 : 40|8@1+ (1,0) [0|255] ""  SBMU
 SG_ M2S_CMD2_Data7_11 : 48|8@1+ (1,0) [0|255] ""  SBMU
 SG_ M2S_CMD2_Data8_11 : 56|8@1+ (1,0) [0|255] ""  SBMU

BO_ 2148695964 M2S_CMD2__12: 8 MBMU
 SG_ M2S_CMD2_CRC_12 : 0|8@1+ (1,0) [0|255] ""  SBMU
 SG_ M2S_CMD2_ALIV_12 : 8|4@1+ (1,0) [0|15] ""  SBMU
 SG_ M2S_CMD2_PowerDown_12 : 12|2@1+ (1,0) [0|3] ""  SBMU
 SG_ M2S_CMD2_FanCtrl_12 : 14|1@1+ (1,0) [0|1] ""  SBMU
 SG_ M2S_CMD2_SleepCsc_12 : 15|1@1+ (1,0) [0|1] ""  SBMU
 SG_ M2S_CMD2_Data3_12 : 16|8@1+ (1,0) [0|255] ""  SBMU
 SG_ M2S_CMD2_FullChgFlgFromMBMU_12 : 24|6@1+ (1,0) [0|63] ""  SBMU
 SG_ M2S_CMD2_Data4_12 : 30|2@1+ (1,0) [0|3] ""  SBMU
 SG_ M2S_MinSBMUAveTmpValue_12 : 32|8@1+ (1,-50) [-50|205] ""  SBMU
 SG_ M2S_CMD2_Data6_12 : 40|8@1+ (1,0) [0|255] ""  SBMU
 SG_ M2S_CMD2_Data7_12 : 48|8@1+ (1,0) [0|255] ""  SBMU
 SG_ M2S_CMD2_Data8_12 : 56|8@1+ (1,0) [0|255] ""  SBMU

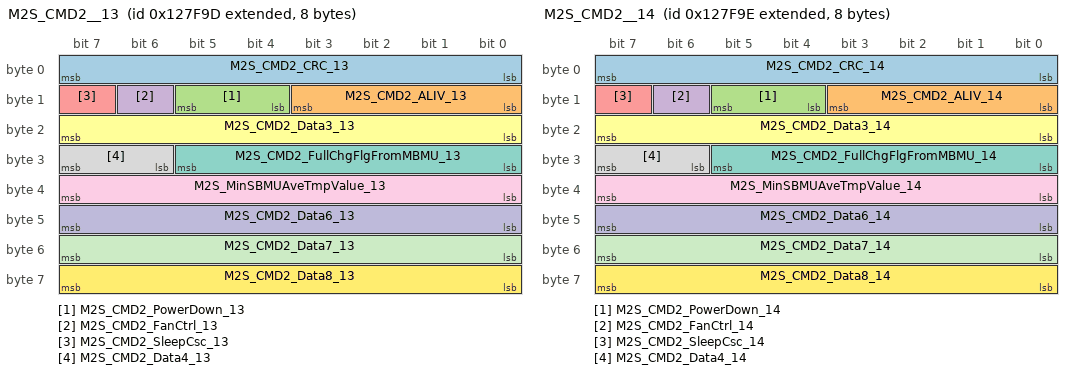
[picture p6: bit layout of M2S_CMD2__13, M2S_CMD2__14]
BO_ 2148695965 M2S_CMD2__13: 8 MBMU
 SG_ M2S_CMD2_CRC_13 : 0|8@1+ (1,0) [0|255] ""  SBMU
 SG_ M2S_CMD2_ALIV_13 : 8|4@1+ (1,0) [0|15] ""  SBMU
 SG_ M2S_CMD2_PowerDown_13 : 12|2@1+ (1,0) [0|3] ""  SBMU
 SG_ M2S_CMD2_FanCtrl_13 : 14|1@1+ (1,0) [0|1] ""  SBMU
 SG_ M2S_CMD2_SleepCsc_13 : 15|1@1+ (1,0) [0|1] ""  SBMU
 SG_ M2S_CMD2_Data3_13 : 16|8@1+ (1,0) [0|255] ""  SBMU
 SG_ M2S_CMD2_FullChgFlgFromMBMU_13 : 24|6@1+ (1,0) [0|63] ""  SBMU
 SG_ M2S_CMD2_Data4_13 : 30|2@1+ (1,0) [0|3] ""  SBMU
 SG_ M2S_MinSBMUAveTmpValue_13 : 32|8@1+ (1,-50) [-50|205] ""  SBMU
 SG_ M2S_CMD2_Data6_13 : 40|8@1+ (1,0) [0|255] ""  SBMU
 SG_ M2S_CMD2_Data7_13 : 48|8@1+ (1,0) [0|255] ""  SBMU
 SG_ M2S_CMD2_Data8_13 : 56|8@1+ (1,0) [0|255] ""  SBMU

BO_ 2148695966 M2S_CMD2__14: 8 MBMU
 SG_ M2S_CMD2_CRC_14 : 0|8@1+ (1,0) [0|255] ""  SBMU
 SG_ M2S_CMD2_ALIV_14 : 8|4@1+ (1,0) [0|15] ""  SBMU
 SG_ M2S_CMD2_PowerDown_14 : 12|2@1+ (1,0) [0|3] ""  SBMU
 SG_ M2S_CMD2_FanCtrl_14 : 14|1@1+ (1,0) [0|1] ""  SBMU
 SG_ M2S_CMD2_SleepCsc_14 : 15|1@1+ (1,0) [0|1] ""  SBMU
 SG_ M2S_CMD2_Data3_14 : 16|8@1+ (1,0) [0|255] ""  SBMU
 SG_ M2S_CMD2_FullChgFlgFromMBMU_14 : 24|6@1+ (1,0) [0|63] ""  SBMU
 SG_ M2S_CMD2_Data4_14 : 30|2@1+ (1,0) [0|3] ""  SBMU
 SG_ M2S_MinSBMUAveTmpValue_14 : 32|8@1+ (1,-50) [-50|205] ""  SBMU
 SG_ M2S_CMD2_Data6_14 : 40|8@1+ (1,0) [0|255] ""  SBMU
 SG_ M2S_CMD2_Data7_14 : 48|8@1+ (1,0) [0|255] ""  SBMU
 SG_ M2S_CMD2_Data8_14 : 56|8@1+ (1,0) [0|255] ""  SBMU

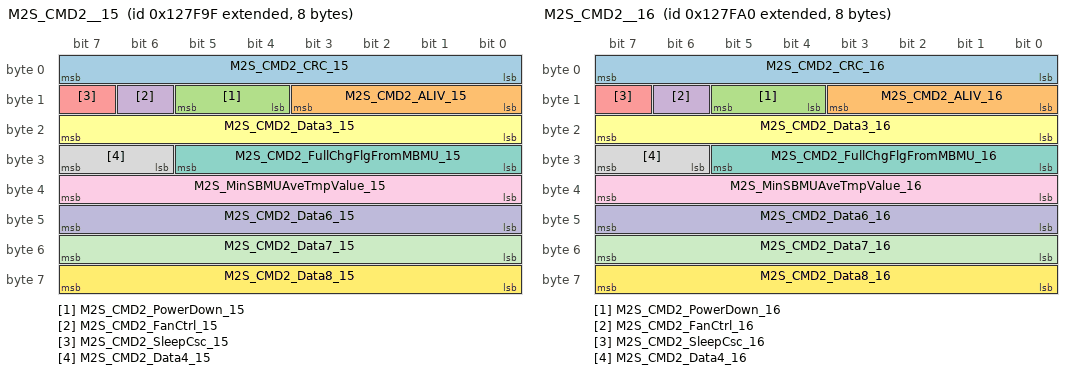
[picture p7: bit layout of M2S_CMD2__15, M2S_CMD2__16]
BO_ 2148695967 M2S_CMD2__15: 8 MBMU
 SG_ M2S_CMD2_CRC_15 : 0|8@1+ (1,0) [0|255] ""  SBMU
 SG_ M2S_CMD2_ALIV_15 : 8|4@1+ (1,0) [0|15] ""  SBMU
 SG_ M2S_CMD2_PowerDown_15 : 12|2@1+ (1,0) [0|3] ""  SBMU
 SG_ M2S_CMD2_FanCtrl_15 : 14|1@1+ (1,0) [0|1] ""  SBMU
 SG_ M2S_CMD2_SleepCsc_15 : 15|1@1+ (1,0) [0|1] ""  SBMU
 SG_ M2S_CMD2_Data3_15 : 16|8@1+ (1,0) [0|255] ""  SBMU
 SG_ M2S_CMD2_FullChgFlgFromMBMU_15 : 24|6@1+ (1,0) [0|63] ""  SBMU
 SG_ M2S_CMD2_Data4_15 : 30|2@1+ (1,0) [0|3] ""  SBMU
 SG_ M2S_MinSBMUAveTmpValue_15 : 32|8@1+ (1,-50) [-50|205] ""  SBMU
 SG_ M2S_CMD2_Data6_15 : 40|8@1+ (1,0) [0|255] ""  SBMU
 SG_ M2S_CMD2_Data7_15 : 48|8@1+ (1,0) [0|255] ""  SBMU
 SG_ M2S_CMD2_Data8_15 : 56|8@1+ (1,0) [0|255] ""  SBMU

BO_ 2148695968 M2S_CMD2__16: 8 MBMU
 SG_ M2S_CMD2_CRC_16 : 0|8@1+ (1,0) [0|255] ""  SBMU
 SG_ M2S_CMD2_ALIV_16 : 8|4@1+ (1,0) [0|15] ""  SBMU
 SG_ M2S_CMD2_PowerDown_16 : 12|2@1+ (1,0) [0|3] ""  SBMU
 SG_ M2S_CMD2_FanCtrl_16 : 14|1@1+ (1,0) [0|1] ""  SBMU
 SG_ M2S_CMD2_SleepCsc_16 : 15|1@1+ (1,0) [0|1] ""  SBMU
 SG_ M2S_CMD2_Data3_16 : 16|8@1+ (1,0) [0|255] ""  SBMU
 SG_ M2S_CMD2_FullChgFlgFromMBMU_16 : 24|6@1+ (1,0) [0|63] ""  SBMU
 SG_ M2S_CMD2_Data4_16 : 30|2@1+ (1,0) [0|3] ""  SBMU
 SG_ M2S_MinSBMUAveTmpValue_16 : 32|8@1+ (1,-50) [-50|205] ""  SBMU
 SG_ M2S_CMD2_Data6_16 : 40|8@1+ (1,0) [0|255] ""  SBMU
 SG_ M2S_CMD2_Data7_16 : 48|8@1+ (1,0) [0|255] ""  SBMU
 SG_ M2S_CMD2_Data8_16 : 56|8@1+ (1,0) [0|255] ""  SBMU

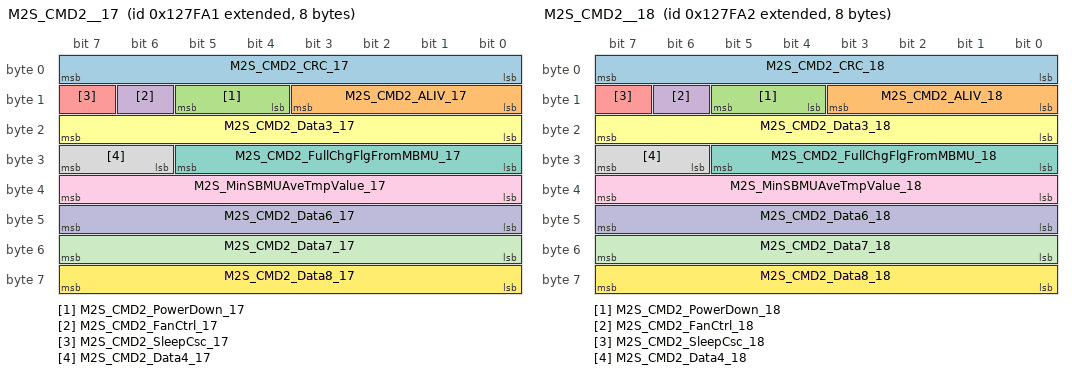
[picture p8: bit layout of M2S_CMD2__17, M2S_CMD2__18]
BO_ 2148695969 M2S_CMD2__17: 8 MBMU
 SG_ M2S_CMD2_CRC_17 : 0|8@1+ (1,0) [0|255] ""  SBMU
 SG_ M2S_CMD2_ALIV_17 : 8|4@1+ (1,0) [0|15] ""  SBMU
 SG_ M2S_CMD2_PowerDown_17 : 12|2@1+ (1,0) [0|3] ""  SBMU
 SG_ M2S_CMD2_FanCtrl_17 : 14|1@1+ (1,0) [0|1] ""  SBMU
 SG_ M2S_CMD2_SleepCsc_17 : 15|1@1+ (1,0) [0|1] ""  SBMU
 SG_ M2S_CMD2_Data3_17 : 16|8@1+ (1,0) [0|255] ""  SBMU
 SG_ M2S_CMD2_FullChgFlgFromMBMU_17 : 24|6@1+ (1,0) [0|63] ""  SBMU
 SG_ M2S_CMD2_Data4_17 : 30|2@1+ (1,0) [0|3] ""  SBMU
 SG_ M2S_MinSBMUAveTmpValue_17 : 32|8@1+ (1,-50) [-50|205] ""  SBMU
 SG_ M2S_CMD2_Data6_17 : 40|8@1+ (1,0) [0|255] ""  SBMU
 SG_ M2S_CMD2_Data7_17 : 48|8@1+ (1,0) [0|255] ""  SBMU
 SG_ M2S_CMD2_Data8_17 : 56|8@1+ (1,0) [0|255] ""  SBMU

BO_ 2148695970 M2S_CMD2__18: 8 MBMU
 SG_ M2S_CMD2_CRC_18 : 0|8@1+ (1,0) [0|255] ""  SBMU
 SG_ M2S_CMD2_ALIV_18 : 8|4@1+ (1,0) [0|15] ""  SBMU
 SG_ M2S_CMD2_PowerDown_18 : 12|2@1+ (1,0) [0|3] ""  SBMU
 SG_ M2S_CMD2_FanCtrl_18 : 14|1@1+ (1,0) [0|1] ""  SBMU
 SG_ M2S_CMD2_SleepCsc_18 : 15|1@1+ (1,0) [0|1] ""  SBMU
 SG_ M2S_CMD2_Data3_18 : 16|8@1+ (1,0) [0|255] ""  SBMU
 SG_ M2S_CMD2_FullChgFlgFromMBMU_18 : 24|6@1+ (1,0) [0|63] ""  SBMU
 SG_ M2S_CMD2_Data4_18 : 30|2@1+ (1,0) [0|3] ""  SBMU
 SG_ M2S_MinSBMUAveTmpValue_18 : 32|8@1+ (1,-50) [-50|205] ""  SBMU
 SG_ M2S_CMD2_Data6_18 : 40|8@1+ (1,0) [0|255] ""  SBMU
 SG_ M2S_CMD2_Data7_18 : 48|8@1+ (1,0) [0|255] ""  SBMU
 SG_ M2S_CMD2_Data8_18 : 56|8@1+ (1,0) [0|255] ""  SBMU

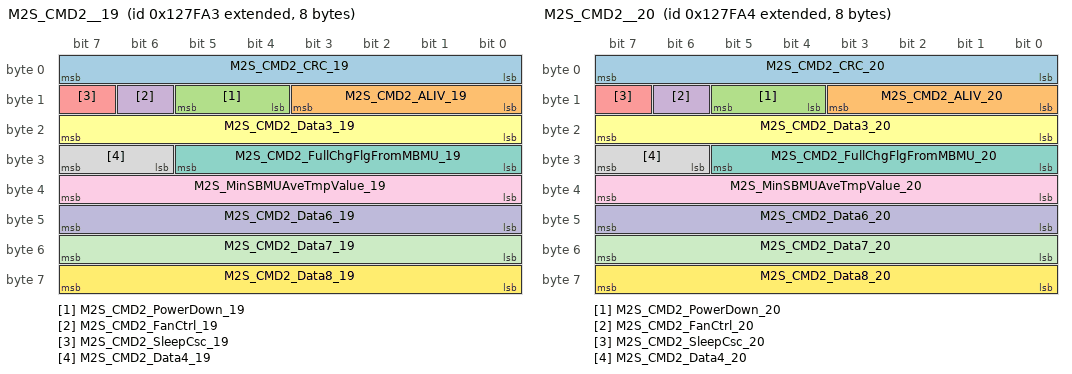
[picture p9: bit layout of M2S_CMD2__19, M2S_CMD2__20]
BO_ 2148695971 M2S_CMD2__19: 8 MBMU
 SG_ M2S_CMD2_CRC_19 : 0|8@1+ (1,0) [0|255] ""  SBMU
 SG_ M2S_CMD2_ALIV_19 : 8|4@1+ (1,0) [0|15] ""  SBMU
 SG_ M2S_CMD2_PowerDown_19 : 12|2@1+ (1,0) [0|3] ""  SBMU
 SG_ M2S_CMD2_FanCtrl_19 : 14|1@1+ (1,0) [0|1] ""  SBMU
 SG_ M2S_CMD2_SleepCsc_19 : 15|1@1+ (1,0) [0|1] ""  SBMU
 SG_ M2S_CMD2_Data3_19 : 16|8@1+ (1,0) [0|255] ""  SBMU
 SG_ M2S_CMD2_FullChgFlgFromMBMU_19 : 24|6@1+ (1,0) [0|63] ""  SBMU
 SG_ M2S_CMD2_Data4_19 : 30|2@1+ (1,0) [0|3] ""  SBMU
 SG_ M2S_MinSBMUAveTmpValue_19 : 32|8@1+ (1,-50) [-50|205] ""  SBMU
 SG_ M2S_CMD2_Data6_19 : 40|8@1+ (1,0) [0|255] ""  SBMU
 SG_ M2S_CMD2_Data7_19 : 48|8@1+ (1,0) [0|255] ""  SBMU
 SG_ M2S_CMD2_Data8_19 : 56|8@1+ (1,0) [0|255] ""  SBMU

BO_ 2148695972 M2S_CMD2__20: 8 MBMU
 SG_ M2S_CMD2_CRC_20 : 0|8@1+ (1,0) [0|255] ""  SBMU
 SG_ M2S_CMD2_ALIV_20 : 8|4@1+ (1,0) [0|15] ""  SBMU
 SG_ M2S_CMD2_PowerDown_20 : 12|2@1+ (1,0) [0|3] ""  SBMU
 SG_ M2S_CMD2_FanCtrl_20 : 14|1@1+ (1,0) [0|1] ""  SBMU
 SG_ M2S_CMD2_SleepCsc_20 : 15|1@1+ (1,0) [0|1] ""  SBMU
 SG_ M2S_CMD2_Data3_20 : 16|8@1+ (1,0) [0|255] ""  SBMU
 SG_ M2S_CMD2_FullChgFlgFromMBMU_20 : 24|6@1+ (1,0) [0|63] ""  SBMU
 SG_ M2S_CMD2_Data4_20 : 30|2@1+ (1,0) [0|3] ""  SBMU
 SG_ M2S_MinSBMUAveTmpValue_20 : 32|8@1+ (1,-50) [-50|205] ""  SBMU
 SG_ M2S_CMD2_Data6_20 : 40|8@1+ (1,0) [0|255] ""  SBMU
 SG_ M2S_CMD2_Data7_20 : 48|8@1+ (1,0) [0|255] ""  SBMU
 SG_ M2S_CMD2_Data8_20 : 56|8@1+ (1,0) [0|255] ""  SBMU

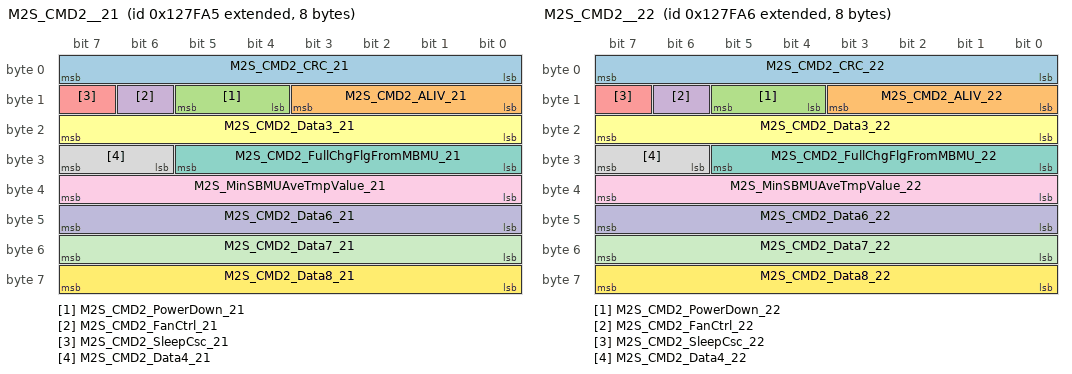
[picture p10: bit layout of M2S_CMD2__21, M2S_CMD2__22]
BO_ 2148695973 M2S_CMD2__21: 8 MBMU
 SG_ M2S_CMD2_CRC_21 : 0|8@1+ (1,0) [0|255] ""  SBMU
 SG_ M2S_CMD2_ALIV_21 : 8|4@1+ (1,0) [0|15] ""  SBMU
 SG_ M2S_CMD2_PowerDown_21 : 12|2@1+ (1,0) [0|3] ""  SBMU
 SG_ M2S_CMD2_FanCtrl_21 : 14|1@1+ (1,0) [0|1] ""  SBMU
 SG_ M2S_CMD2_SleepCsc_21 : 15|1@1+ (1,0) [0|1] ""  SBMU
 SG_ M2S_CMD2_Data3_21 : 16|8@1+ (1,0) [0|255] ""  SBMU
 SG_ M2S_CMD2_FullChgFlgFromMBMU_21 : 24|6@1+ (1,0) [0|63] ""  SBMU
 SG_ M2S_CMD2_Data4_21 : 30|2@1+ (1,0) [0|3] ""  SBMU
 SG_ M2S_MinSBMUAveTmpValue_21 : 32|8@1+ (1,-50) [-50|205] ""  SBMU
 SG_ M2S_CMD2_Data6_21 : 40|8@1+ (1,0) [0|255] ""  SBMU
 SG_ M2S_CMD2_Data7_21 : 48|8@1+ (1,0) [0|255] ""  SBMU
 SG_ M2S_CMD2_Data8_21 : 56|8@1+ (1,0) [0|255] ""  SBMU

BO_ 2148695974 M2S_CMD2__22: 8 MBMU
 SG_ M2S_CMD2_CRC_22 : 0|8@1+ (1,0) [0|255] ""  SBMU
 SG_ M2S_CMD2_ALIV_22 : 8|4@1+ (1,0) [0|15] ""  SBMU
 SG_ M2S_CMD2_PowerDown_22 : 12|2@1+ (1,0) [0|3] ""  SBMU
 SG_ M2S_CMD2_FanCtrl_22 : 14|1@1+ (1,0) [0|1] ""  SBMU
 SG_ M2S_CMD2_SleepCsc_22 : 15|1@1+ (1,0) [0|1] ""  SBMU
 SG_ M2S_CMD2_Data3_22 : 16|8@1+ (1,0) [0|255] ""  SBMU
 SG_ M2S_CMD2_FullChgFlgFromMBMU_22 : 24|6@1+ (1,0) [0|63] ""  SBMU
 SG_ M2S_CMD2_Data4_22 : 30|2@1+ (1,0) [0|3] ""  SBMU
 SG_ M2S_MinSBMUAveTmpValue_22 : 32|8@1+ (1,-50) [-50|205] ""  SBMU
 SG_ M2S_CMD2_Data6_22 : 40|8@1+ (1,0) [0|255] ""  SBMU
 SG_ M2S_CMD2_Data7_22 : 48|8@1+ (1,0) [0|255] ""  SBMU
 SG_ M2S_CMD2_Data8_22 : 56|8@1+ (1,0) [0|255] ""  SBMU

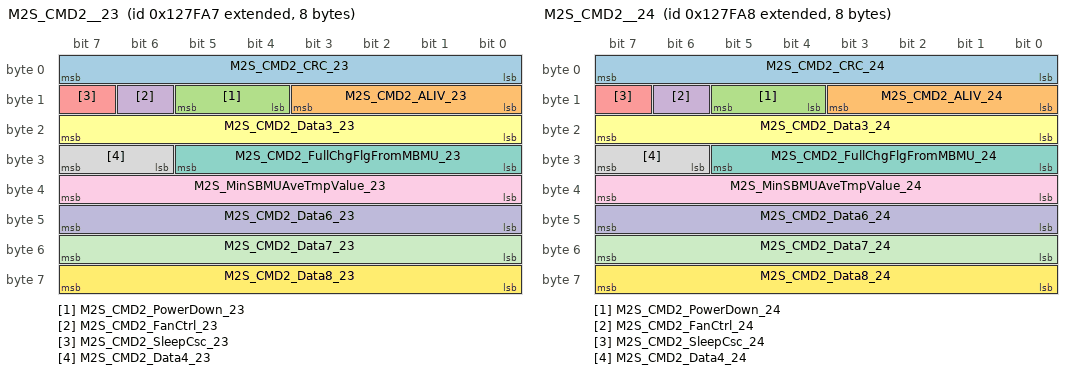
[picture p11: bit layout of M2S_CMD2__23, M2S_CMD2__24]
BO_ 2148695975 M2S_CMD2__23: 8 MBMU
 SG_ M2S_CMD2_CRC_23 : 0|8@1+ (1,0) [0|255] ""  SBMU
 SG_ M2S_CMD2_ALIV_23 : 8|4@1+ (1,0) [0|15] ""  SBMU
 SG_ M2S_CMD2_PowerDown_23 : 12|2@1+ (1,0) [0|3] ""  SBMU
 SG_ M2S_CMD2_FanCtrl_23 : 14|1@1+ (1,0) [0|1] ""  SBMU
 SG_ M2S_CMD2_SleepCsc_23 : 15|1@1+ (1,0) [0|1] ""  SBMU
 SG_ M2S_CMD2_Data3_23 : 16|8@1+ (1,0) [0|255] ""  SBMU
 SG_ M2S_CMD2_FullChgFlgFromMBMU_23 : 24|6@1+ (1,0) [0|63] ""  SBMU
 SG_ M2S_CMD2_Data4_23 : 30|2@1+ (1,0) [0|3] ""  SBMU
 SG_ M2S_MinSBMUAveTmpValue_23 : 32|8@1+ (1,-50) [-50|205] ""  SBMU
 SG_ M2S_CMD2_Data6_23 : 40|8@1+ (1,0) [0|255] ""  SBMU
 SG_ M2S_CMD2_Data7_23 : 48|8@1+ (1,0) [0|255] ""  SBMU
 SG_ M2S_CMD2_Data8_23 : 56|8@1+ (1,0) [0|255] ""  SBMU

BO_ 2148695976 M2S_CMD2__24: 8 MBMU
 SG_ M2S_CMD2_CRC_24 : 0|8@1+ (1,0) [0|255] ""  SBMU
 SG_ M2S_CMD2_ALIV_24 : 8|4@1+ (1,0) [0|15] ""  SBMU
 SG_ M2S_CMD2_PowerDown_24 : 12|2@1+ (1,0) [0|3] ""  SBMU
 SG_ M2S_CMD2_FanCtrl_24 : 14|1@1+ (1,0) [0|1] ""  SBMU
 SG_ M2S_CMD2_SleepCsc_24 : 15|1@1+ (1,0) [0|1] ""  SBMU
 SG_ M2S_CMD2_Data3_24 : 16|8@1+ (1,0) [0|255] ""  SBMU
 SG_ M2S_CMD2_FullChgFlgFromMBMU_24 : 24|6@1+ (1,0) [0|63] ""  SBMU
 SG_ M2S_CMD2_Data4_24 : 30|2@1+ (1,0) [0|3] ""  SBMU
 SG_ M2S_MinSBMUAveTmpValue_24 : 32|8@1+ (1,-50) [-50|205] ""  SBMU
 SG_ M2S_CMD2_Data6_24 : 40|8@1+ (1,0) [0|255] ""  SBMU
 SG_ M2S_CMD2_Data7_24 : 48|8@1+ (1,0) [0|255] ""  SBMU
 SG_ M2S_CMD2_Data8_24 : 56|8@1+ (1,0) [0|255] ""  SBMU

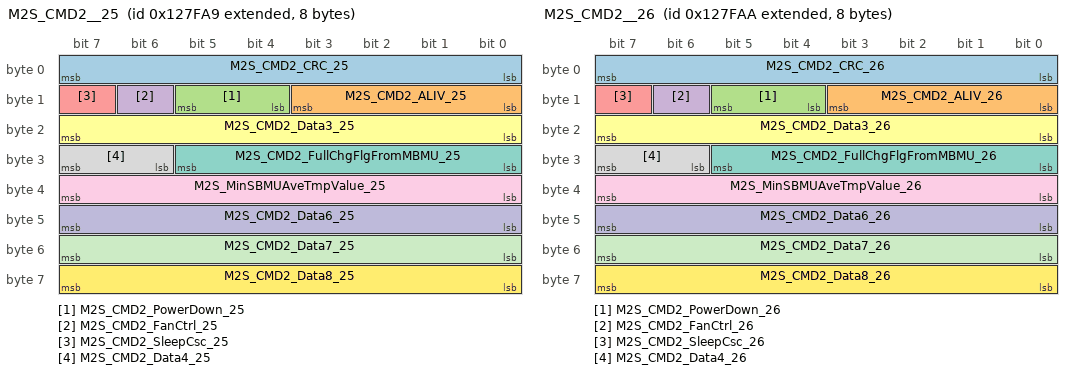
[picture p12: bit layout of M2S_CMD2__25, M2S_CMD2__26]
BO_ 2148695977 M2S_CMD2__25: 8 MBMU
 SG_ M2S_CMD2_CRC_25 : 0|8@1+ (1,0) [0|255] ""  SBMU
 SG_ M2S_CMD2_ALIV_25 : 8|4@1+ (1,0) [0|15] ""  SBMU
 SG_ M2S_CMD2_PowerDown_25 : 12|2@1+ (1,0) [0|3] ""  SBMU
 SG_ M2S_CMD2_FanCtrl_25 : 14|1@1+ (1,0) [0|1] ""  SBMU
 SG_ M2S_CMD2_SleepCsc_25 : 15|1@1+ (1,0) [0|1] ""  SBMU
 SG_ M2S_CMD2_Data3_25 : 16|8@1+ (1,0) [0|255] ""  SBMU
 SG_ M2S_CMD2_FullChgFlgFromMBMU_25 : 24|6@1+ (1,0) [0|63] ""  SBMU
 SG_ M2S_CMD2_Data4_25 : 30|2@1+ (1,0) [0|3] ""  SBMU
 SG_ M2S_MinSBMUAveTmpValue_25 : 32|8@1+ (1,-50) [-50|205] ""  SBMU
 SG_ M2S_CMD2_Data6_25 : 40|8@1+ (1,0) [0|255] ""  SBMU
 SG_ M2S_CMD2_Data7_25 : 48|8@1+ (1,0) [0|255] ""  SBMU
 SG_ M2S_CMD2_Data8_25 : 56|8@1+ (1,0) [0|255] ""  SBMU

BO_ 2148695978 M2S_CMD2__26: 8 MBMU
 SG_ M2S_CMD2_CRC_26 : 0|8@1+ (1,0) [0|255] ""  SBMU
 SG_ M2S_CMD2_ALIV_26 : 8|4@1+ (1,0) [0|15] ""  SBMU
 SG_ M2S_CMD2_PowerDown_26 : 12|2@1+ (1,0) [0|3] ""  SBMU
 SG_ M2S_CMD2_FanCtrl_26 : 14|1@1+ (1,0) [0|1] ""  SBMU
 SG_ M2S_CMD2_SleepCsc_26 : 15|1@1+ (1,0) [0|1] ""  SBMU
 SG_ M2S_CMD2_Data3_26 : 16|8@1+ (1,0) [0|255] ""  SBMU
 SG_ M2S_CMD2_FullChgFlgFromMBMU_26 : 24|6@1+ (1,0) [0|63] ""  SBMU
 SG_ M2S_CMD2_Data4_26 : 30|2@1+ (1,0) [0|3] ""  SBMU
 SG_ M2S_MinSBMUAveTmpValue_26 : 32|8@1+ (1,-50) [-50|205] ""  SBMU
 SG_ M2S_CMD2_Data6_26 : 40|8@1+ (1,0) [0|255] ""  SBMU
 SG_ M2S_CMD2_Data7_26 : 48|8@1+ (1,0) [0|255] ""  SBMU
 SG_ M2S_CMD2_Data8_26 : 56|8@1+ (1,0) [0|255] ""  SBMU

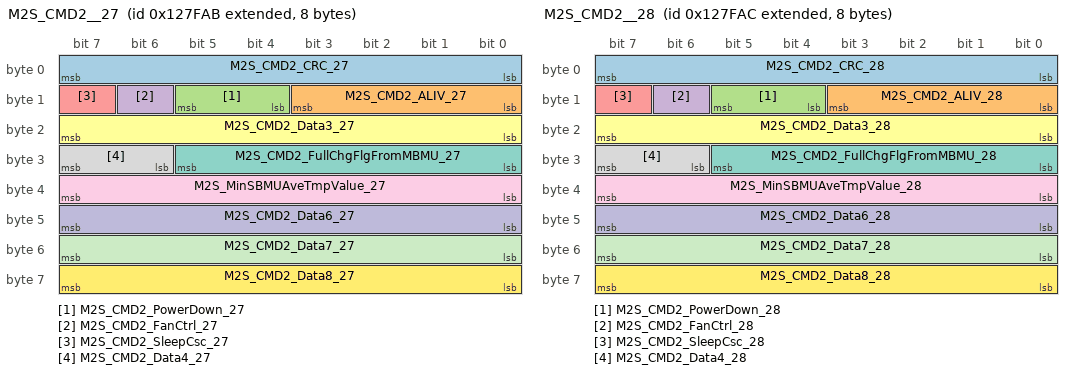
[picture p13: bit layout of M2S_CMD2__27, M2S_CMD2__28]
BO_ 2148695979 M2S_CMD2__27: 8 MBMU
 SG_ M2S_CMD2_CRC_27 : 0|8@1+ (1,0) [0|255] ""  SBMU
 SG_ M2S_CMD2_ALIV_27 : 8|4@1+ (1,0) [0|15] ""  SBMU
 SG_ M2S_CMD2_PowerDown_27 : 12|2@1+ (1,0) [0|3] ""  SBMU
 SG_ M2S_CMD2_FanCtrl_27 : 14|1@1+ (1,0) [0|1] ""  SBMU
 SG_ M2S_CMD2_SleepCsc_27 : 15|1@1+ (1,0) [0|1] ""  SBMU
 SG_ M2S_CMD2_Data3_27 : 16|8@1+ (1,0) [0|255] ""  SBMU
 SG_ M2S_CMD2_FullChgFlgFromMBMU_27 : 24|6@1+ (1,0) [0|63] ""  SBMU
 SG_ M2S_CMD2_Data4_27 : 30|2@1+ (1,0) [0|3] ""  SBMU
 SG_ M2S_MinSBMUAveTmpValue_27 : 32|8@1+ (1,-50) [-50|205] ""  SBMU
 SG_ M2S_CMD2_Data6_27 : 40|8@1+ (1,0) [0|255] ""  SBMU
 SG_ M2S_CMD2_Data7_27 : 48|8@1+ (1,0) [0|255] ""  SBMU
 SG_ M2S_CMD2_Data8_27 : 56|8@1+ (1,0) [0|255] ""  SBMU

BO_ 2148695980 M2S_CMD2__28: 8 MBMU
 SG_ M2S_CMD2_CRC_28 : 0|8@1+ (1,0) [0|255] ""  SBMU
 SG_ M2S_CMD2_ALIV_28 : 8|4@1+ (1,0) [0|15] ""  SBMU
 SG_ M2S_CMD2_PowerDown_28 : 12|2@1+ (1,0) [0|3] ""  SBMU
 SG_ M2S_CMD2_FanCtrl_28 : 14|1@1+ (1,0) [0|1] ""  SBMU
 SG_ M2S_CMD2_SleepCsc_28 : 15|1@1+ (1,0) [0|1] ""  SBMU
 SG_ M2S_CMD2_Data3_28 : 16|8@1+ (1,0) [0|255] ""  SBMU
 SG_ M2S_CMD2_FullChgFlgFromMBMU_28 : 24|6@1+ (1,0) [0|63] ""  SBMU
 SG_ M2S_CMD2_Data4_28 : 30|2@1+ (1,0) [0|3] ""  SBMU
 SG_ M2S_MinSBMUAveTmpValue_28 : 32|8@1+ (1,-50) [-50|205] ""  SBMU
 SG_ M2S_CMD2_Data6_28 : 40|8@1+ (1,0) [0|255] ""  SBMU
 SG_ M2S_CMD2_Data7_28 : 48|8@1+ (1,0) [0|255] ""  SBMU
 SG_ M2S_CMD2_Data8_28 : 56|8@1+ (1,0) [0|255] ""  SBMU

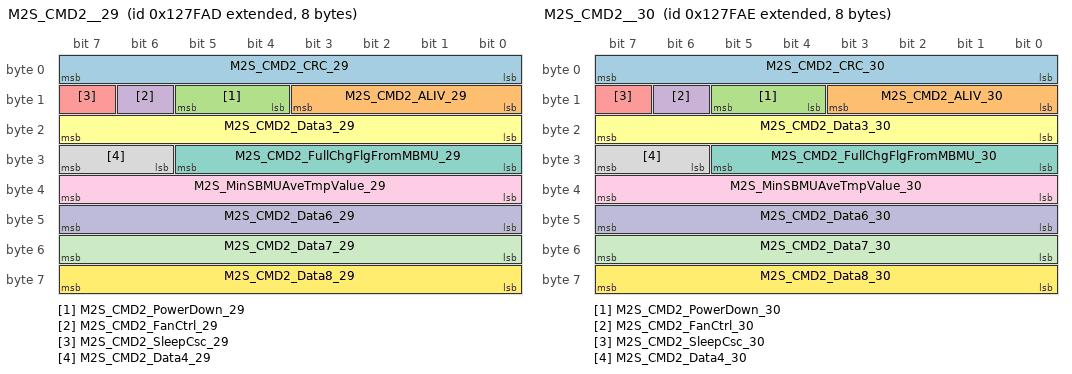
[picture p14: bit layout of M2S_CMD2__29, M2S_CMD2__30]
BO_ 2148695981 M2S_CMD2__29: 8 MBMU
 SG_ M2S_CMD2_CRC_29 : 0|8@1+ (1,0) [0|255] ""  SBMU
 SG_ M2S_CMD2_ALIV_29 : 8|4@1+ (1,0) [0|15] ""  SBMU
 SG_ M2S_CMD2_PowerDown_29 : 12|2@1+ (1,0) [0|3] ""  SBMU
 SG_ M2S_CMD2_FanCtrl_29 : 14|1@1+ (1,0) [0|1] ""  SBMU
 SG_ M2S_CMD2_SleepCsc_29 : 15|1@1+ (1,0) [0|1] ""  SBMU
 SG_ M2S_CMD2_Data3_29 : 16|8@1+ (1,0) [0|255] ""  SBMU
 SG_ M2S_CMD2_FullChgFlgFromMBMU_29 : 24|6@1+ (1,0) [0|63] ""  SBMU
 SG_ M2S_CMD2_Data4_29 : 30|2@1+ (1,0) [0|3] ""  SBMU
 SG_ M2S_MinSBMUAveTmpValue_29 : 32|8@1+ (1,-50) [-50|205] ""  SBMU
 SG_ M2S_CMD2_Data6_29 : 40|8@1+ (1,0) [0|255] ""  SBMU
 SG_ M2S_CMD2_Data7_29 : 48|8@1+ (1,0) [0|255] ""  SBMU
 SG_ M2S_CMD2_Data8_29 : 56|8@1+ (1,0) [0|255] ""  SBMU

BO_ 2148695982 M2S_CMD2__30: 8 MBMU
 SG_ M2S_CMD2_CRC_30 : 0|8@1+ (1,0) [0|255] ""  SBMU
 SG_ M2S_CMD2_ALIV_30 : 8|4@1+ (1,0) [0|15] ""  SBMU
 SG_ M2S_CMD2_PowerDown_30 : 12|2@1+ (1,0) [0|3] ""  SBMU
 SG_ M2S_CMD2_FanCtrl_30 : 14|1@1+ (1,0) [0|1] ""  SBMU
 SG_ M2S_CMD2_SleepCsc_30 : 15|1@1+ (1,0) [0|1] ""  SBMU
 SG_ M2S_CMD2_Data3_30 : 16|8@1+ (1,0) [0|255] ""  SBMU
 SG_ M2S_CMD2_FullChgFlgFromMBMU_30 : 24|6@1+ (1,0) [0|63] ""  SBMU
 SG_ M2S_CMD2_Data4_30 : 30|2@1+ (1,0) [0|3] ""  SBMU
 SG_ M2S_MinSBMUAveTmpValue_30 : 32|8@1+ (1,-50) [-50|205] ""  SBMU
 SG_ M2S_CMD2_Data6_30 : 40|8@1+ (1,0) [0|255] ""  SBMU
 SG_ M2S_CMD2_Data7_30 : 48|8@1+ (1,0) [0|255] ""  SBMU
 SG_ M2S_CMD2_Data8_30 : 56|8@1+ (1,0) [0|255] ""  SBMU

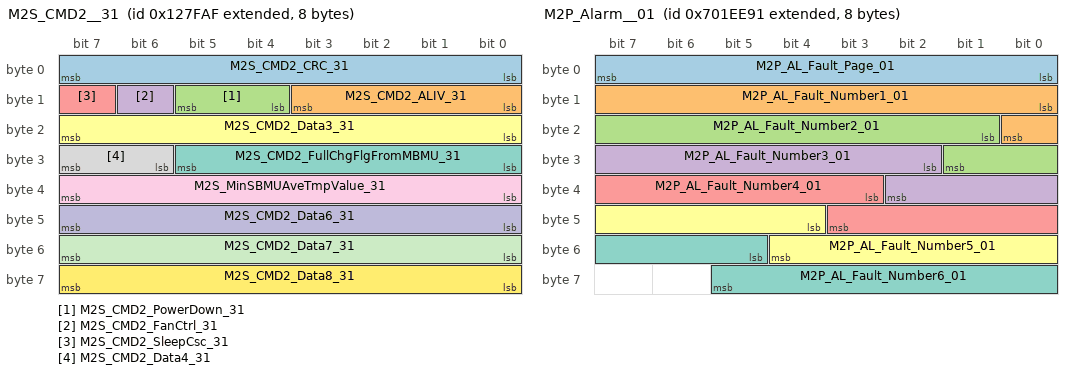
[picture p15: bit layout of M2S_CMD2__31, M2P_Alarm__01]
BO_ 2148695983 M2S_CMD2__31: 8 MBMU
 SG_ M2S_CMD2_CRC_31 : 0|8@1+ (1,0) [0|255] ""  SBMU
 SG_ M2S_CMD2_ALIV_31 : 8|4@1+ (1,0) [0|15] ""  SBMU
 SG_ M2S_CMD2_PowerDown_31 : 12|2@1+ (1,0) [0|3] ""  SBMU
 SG_ M2S_CMD2_FanCtrl_31 : 14|1@1+ (1,0) [0|1] ""  SBMU
 SG_ M2S_CMD2_SleepCsc_31 : 15|1@1+ (1,0) [0|1] ""  SBMU
 SG_ M2S_CMD2_Data3_31 : 16|8@1+ (1,0) [0|255] ""  SBMU
 SG_ M2S_CMD2_FullChgFlgFromMBMU_31 : 24|6@1+ (1,0) [0|63] ""  SBMU
 SG_ M2S_CMD2_Data4_31 : 30|2@1+ (1,0) [0|3] ""  SBMU
 SG_ M2S_MinSBMUAveTmpValue_31 : 32|8@1+ (1,-50) [-50|205] ""  SBMU
 SG_ M2S_CMD2_Data6_31 : 40|8@1+ (1,0) [0|255] ""  SBMU
 SG_ M2S_CMD2_Data7_31 : 48|8@1+ (1,0) [0|255] ""  SBMU
 SG_ M2S_CMD2_Data8_31 : 56|8@1+ (1,0) [0|255] ""  SBMU

BO_ 2148761489 M2S_CMD3__01: 8 MBMU
 SG_ M2S_CMD3_TankNo_01 : 0|8@1+ (1,0) [0|255] ""  SBMU
 SG_ M2S_CMD3_KcFactor_01 : 8|16@1+ (1024,0) [0|67107840] ""  SBMU
 SG_ M2S_CMD3_KdFactor_01 : 24|16@1+ (1024,0) [0|67107840] ""  SBMU
 SG_ M2S_CMD3_TankSOC_01 : 40|16@1+ (0.1,0) [0|100] "%"  SBMU
 SG_ M2S_CMD3_SOCCmd_01 : 56|8@1+ (1,0) [0|255] ""  SBMU

BO_ 2148761490 M2S_CMD3__02: 8 MBMU
 SG_ M2S_CMD3_TankNo_02 : 0|8@1+ (1,0) [0|255] ""  SBMU
 SG_ M2S_CMD3_KcFactor_02 : 8|16@1+ (1024,0) [0|67107840] ""  SBMU
 SG_ M2S_CMD3_KdFactor_02 : 24|16@1+ (1024,0) [0|67107840] ""  SBMU
 SG_ M2S_CMD3_TankSOC_02 : 40|16@1+ (0.1,0) [0|100] "%"  SBMU
 SG_ M2S_CMD3_SOCCmd_02 : 56|8@1+ (1,0) [0|255] ""  SBMU

BO_ 2148761491 M2S_CMD3__03: 8 MBMU
 SG_ M2S_CMD3_TankNo_03 : 0|8@1+ (1,0) [0|255] ""  SBMU
 SG_ M2S_CMD3_KcFactor_03 : 8|16@1+ (1024,0) [0|67107840] ""  SBMU
 SG_ M2S_CMD3_KdFactor_03 : 24|16@1+ (1024,0) [0|67107840] ""  SBMU
 SG_ M2S_CMD3_TankSOC_03 : 40|16@1+ (0.1,0) [0|100] "%"  SBMU
 SG_ M2S_CMD3_SOCCmd_03 : 56|8@1+ (1,0) [0|255] ""  SBMU

BO_ 2148761492 M2S_CMD3__04: 8 MBMU
 SG_ M2S_CMD3_TankNo_04 : 0|8@1+ (1,0) [0|255] ""  SBMU
 SG_ M2S_CMD3_KcFactor_04 : 8|16@1+ (1024,0) [0|67107840] ""  SBMU
 SG_ M2S_CMD3_KdFactor_04 : 24|16@1+ (1024,0) [0|67107840] ""  SBMU
 SG_ M2S_CMD3_TankSOC_04 : 40|16@1+ (0.1,0) [0|100] "%"  SBMU
 SG_ M2S_CMD3_SOCCmd_04 : 56|8@1+ (1,0) [0|255] ""  SBMU

BO_ 2148761493 M2S_CMD3__05: 8 MBMU
 SG_ M2S_CMD3_TankNo_05 : 0|8@1+ (1,0) [0|255] ""  SBMU
 SG_ M2S_CMD3_KcFactor_05 : 8|16@1+ (1024,0) [0|67107840] ""  SBMU
 SG_ M2S_CMD3_KdFactor_05 : 24|16@1+ (1024,0) [0|67107840] ""  SBMU
 SG_ M2S_CMD3_TankSOC_05 : 40|16@1+ (0.1,0) [0|100] "%"  SBMU
 SG_ M2S_CMD3_SOCCmd_05 : 56|8@1+ (1,0) [0|255] ""  SBMU

BO_ 2148761494 M2S_CMD3__06: 8 MBMU
 SG_ M2S_CMD3_TankNo_06 : 0|8@1+ (1,0) [0|255] ""  SBMU
 SG_ M2S_CMD3_KcFactor_06 : 8|16@1+ (1024,0) [0|67107840] ""  SBMU
 SG_ M2S_CMD3_KdFactor_06 : 24|16@1+ (1024,0) [0|67107840] ""  SBMU
 SG_ M2S_CMD3_TankSOC_06 : 40|16@1+ (0.1,0) [0|100] "%"  SBMU
 SG_ M2S_CMD3_SOCCmd_06 : 56|8@1+ (1,0) [0|255] ""  SBMU

BO_ 2148761495 M2S_CMD3__07: 8 MBMU
 SG_ M2S_CMD3_TankNo_07 : 0|8@1+ (1,0) [0|255] ""  SBMU
 SG_ M2S_CMD3_KcFactor_07 : 8|16@1+ (1024,0) [0|67107840] ""  SBMU
 SG_ M2S_CMD3_KdFactor_07 : 24|16@1+ (1024,0) [0|67107840] ""  SBMU
 SG_ M2S_CMD3_TankSOC_07 : 40|16@1+ (0.1,0) [0|100] "%"  SBMU
 SG_ M2S_CMD3_SOCCmd_07 : 56|8@1+ (1,0) [0|255] ""  SBMU

BO_ 2148761496 M2S_CMD3__08: 8 MBMU
 SG_ M2S_CMD3_TankNo_08 : 0|8@1+ (1,0) [0|255] ""  SBMU
 SG_ M2S_CMD3_KcFactor_08 : 8|16@1+ (1024,0) [0|67107840] ""  SBMU
 SG_ M2S_CMD3_KdFactor_08 : 24|16@1+ (1024,0) [0|67107840] ""  SBMU
 SG_ M2S_CMD3_TankSOC_08 : 40|16@1+ (0.1,0) [0|100] "%"  SBMU
 SG_ M2S_CMD3_SOCCmd_08 : 56|8@1+ (1,0) [0|255] ""  SBMU

BO_ 2148761497 M2S_CMD3__09: 8 MBMU
 SG_ M2S_CMD3_TankNo_09 : 0|8@1+ (1,0) [0|255] ""  SBMU
 SG_ M2S_CMD3_KcFactor_09 : 8|16@1+ (1024,0) [0|67107840] ""  SBMU
 SG_ M2S_CMD3_KdFactor_09 : 24|16@1+ (1024,0) [0|67107840] ""  SBMU
 SG_ M2S_CMD3_TankSOC_09 : 40|16@1+ (0.1,0) [0|100] "%"  SBMU
 SG_ M2S_CMD3_SOCCmd_09 : 56|8@1+ (1,0) [0|255] ""  SBMU

BO_ 2148761498 M2S_CMD3__10: 8 MBMU
 SG_ M2S_CMD3_TankNo_10 : 0|8@1+ (1,0) [0|255] ""  SBMU
 SG_ M2S_CMD3_KcFactor_10 : 8|16@1+ (1024,0) [0|67107840] ""  SBMU
 SG_ M2S_CMD3_KdFactor_10 : 24|16@1+ (1024,0) [0|67107840] ""  SBMU
 SG_ M2S_CMD3_TankSOC_10 : 40|16@1+ (0.1,0) [0|100] "%"  SBMU
 SG_ M2S_CMD3_SOCCmd_10 : 56|8@1+ (1,0) [0|255] ""  SBMU

BO_ 2148761499 M2S_CMD3__11: 8 MBMU
 SG_ M2S_CMD3_TankNo_11 : 0|8@1+ (1,0) [0|255] ""  SBMU
 SG_ M2S_CMD3_KcFactor_11 : 8|16@1+ (1024,0) [0|67107840] ""  SBMU
 SG_ M2S_CMD3_KdFactor_11 : 24|16@1+ (1024,0) [0|67107840] ""  SBMU
 SG_ M2S_CMD3_TankSOC_11 : 40|16@1+ (0.1,0) [0|100] "%"  SBMU
 SG_ M2S_CMD3_SOCCmd_11 : 56|8@1+ (1,0) [0|255] ""  SBMU

BO_ 2148761500 M2S_CMD3__12: 8 MBMU
 SG_ M2S_CMD3_TankNo_12 : 0|8@1+ (1,0) [0|255] ""  SBMU
 SG_ M2S_CMD3_KcFactor_12 : 8|16@1+ (1024,0) [0|67107840] ""  SBMU
 SG_ M2S_CMD3_KdFactor_12 : 24|16@1+ (1024,0) [0|67107840] ""  SBMU
 SG_ M2S_CMD3_TankSOC_12 : 40|16@1+ (0.1,0) [0|100] "%"  SBMU
 SG_ M2S_CMD3_SOCCmd_12 : 56|8@1+ (1,0) [0|255] ""  SBMU

BO_ 2148761501 M2S_CMD3__13: 8 MBMU
 SG_ M2S_CMD3_TankNo_13 : 0|8@1+ (1,0) [0|255] ""  SBMU
 SG_ M2S_CMD3_KcFactor_13 : 8|16@1+ (1024,0) [0|67107840] ""  SBMU
 SG_ M2S_CMD3_KdFactor_13 : 24|16@1+ (1024,0) [0|67107840] ""  SBMU
 SG_ M2S_CMD3_TankSOC_13 : 40|16@1+ (0.1,0) [0|100] "%"  SBMU
 SG_ M2S_CMD3_SOCCmd_13 : 56|8@1+ (1,0) [0|255] ""  SBMU

BO_ 2148761502 M2S_CMD3__14: 8 MBMU
 SG_ M2S_CMD3_TankNo_14 : 0|8@1+ (1,0) [0|255] ""  SBMU
 SG_ M2S_CMD3_KcFactor_14 : 8|16@1+ (1024,0) [0|67107840] ""  SBMU
 SG_ M2S_CMD3_KdFactor_14 : 24|16@1+ (1024,0) [0|67107840] ""  SBMU
 SG_ M2S_CMD3_TankSOC_14 : 40|16@1+ (0.1,0) [0|100] "%"  SBMU
 SG_ M2S_CMD3_SOCCmd_14 : 56|8@1+ (1,0) [0|255] ""  SBMU

BO_ 2148761503 M2S_CMD3__15: 8 MBMU
 SG_ M2S_CMD3_TankNo_15 : 0|8@1+ (1,0) [0|255] ""  SBMU
 SG_ M2S_CMD3_KcFactor_15 : 8|16@1+ (1024,0) [0|67107840] ""  SBMU
 SG_ M2S_CMD3_KdFactor_15 : 24|16@1+ (1024,0) [0|67107840] ""  SBMU
 SG_ M2S_CMD3_TankSOC_15 : 40|16@1+ (0.1,0) [0|100] "%"  SBMU
 SG_ M2S_CMD3_SOCCmd_15 : 56|8@1+ (1,0) [0|255] ""  SBMU

BO_ 2148761504 M2S_CMD3__16: 8 MBMU
 SG_ M2S_CMD3_TankNo_16 : 0|8@1+ (1,0) [0|255] ""  SBMU
 SG_ M2S_CMD3_KcFactor_16 : 8|16@1+ (1024,0) [0|67107840] ""  SBMU
 SG_ M2S_CMD3_KdFactor_16 : 24|16@1+ (1024,0) [0|67107840] ""  SBMU
 SG_ M2S_CMD3_TankSOC_16 : 40|16@1+ (0.1,0) [0|100] "%"  SBMU
 SG_ M2S_CMD3_SOCCmd_16 : 56|8@1+ (1,0) [0|255] ""  SBMU

BO_ 2148761505 M2S_CMD3__17: 8 MBMU
 SG_ M2S_CMD3_TankNo_17 : 0|8@1+ (1,0) [0|255] ""  SBMU
 SG_ M2S_CMD3_KcFactor_17 : 8|16@1+ (1024,0) [0|67107840] ""  SBMU
 SG_ M2S_CMD3_KdFactor_17 : 24|16@1+ (1024,0) [0|67107840] ""  SBMU
 SG_ M2S_CMD3_TankSOC_17 : 40|16@1+ (0.1,0) [0|100] "%"  SBMU
 SG_ M2S_CMD3_SOCCmd_17 : 56|8@1+ (1,0) [0|255] ""  SBMU

BO_ 2148761506 M2S_CMD3__18: 8 MBMU
 SG_ M2S_CMD3_TankNo_18 : 0|8@1+ (1,0) [0|255] ""  SBMU
 SG_ M2S_CMD3_KcFactor_18 : 8|16@1+ (1024,0) [0|67107840] ""  SBMU
 SG_ M2S_CMD3_KdFactor_18 : 24|16@1+ (1024,0) [0|67107840] ""  SBMU
 SG_ M2S_CMD3_TankSOC_18 : 40|16@1+ (0.1,0) [0|100] "%"  SBMU
 SG_ M2S_CMD3_SOCCmd_18 : 56|8@1+ (1,0) [0|255] ""  SBMU

BO_ 2148761507 M2S_CMD3__19: 8 MBMU
 SG_ M2S_CMD3_TankNo_19 : 0|8@1+ (1,0) [0|255] ""  SBMU
 SG_ M2S_CMD3_KcFactor_19 : 8|16@1+ (1024,0) [0|67107840] ""  SBMU
 SG_ M2S_CMD3_KdFactor_19 : 24|16@1+ (1024,0) [0|67107840] ""  SBMU
 SG_ M2S_CMD3_TankSOC_19 : 40|16@1+ (0.1,0) [0|100] "%"  SBMU
 SG_ M2S_CMD3_SOCCmd_19 : 56|8@1+ (1,0) [0|255] ""  SBMU

BO_ 2148761508 M2S_CMD3__20: 8 MBMU
 SG_ M2S_CMD3_TankNo_20 : 0|8@1+ (1,0) [0|255] ""  SBMU
 SG_ M2S_CMD3_KcFactor_20 : 8|16@1+ (1024,0) [0|67107840] ""  SBMU
 SG_ M2S_CMD3_KdFactor_20 : 24|16@1+ (1024,0) [0|67107840] ""  SBMU
 SG_ M2S_CMD3_TankSOC_20 : 40|16@1+ (0.1,0) [0|100] "%"  SBMU
 SG_ M2S_CMD3_SOCCmd_20 : 56|8@1+ (1,0) [0|255] ""  SBMU

BO_ 2148761509 M2S_CMD3__21: 8 MBMU
 SG_ M2S_CMD3_TankNo_21 : 0|8@1+ (1,0) [0|255] ""  SBMU
 SG_ M2S_CMD3_KcFactor_21 : 8|16@1+ (1024,0) [0|67107840] ""  SBMU
 SG_ M2S_CMD3_KdFactor_21 : 24|16@1+ (1024,0) [0|67107840] ""  SBMU
 SG_ M2S_CMD3_TankSOC_21 : 40|16@1+ (0.1,0) [0|100] "%"  SBMU
 SG_ M2S_CMD3_SOCCmd_21 : 56|8@1+ (1,0) [0|255] ""  SBMU

BO_ 2148761510 M2S_CMD3__22: 8 MBMU
 SG_ M2S_CMD3_TankNo_22 : 0|8@1+ (1,0) [0|255] ""  SBMU
 SG_ M2S_CMD3_KcFactor_22 : 8|16@1+ (1024,0) [0|67107840] ""  SBMU
 SG_ M2S_CMD3_KdFactor_22 : 24|16@1+ (1024,0) [0|67107840] ""  SBMU
 SG_ M2S_CMD3_TankSOC_22 : 40|16@1+ (0.1,0) [0|100] "%"  SBMU
 SG_ M2S_CMD3_SOCCmd_22 : 56|8@1+ (1,0) [0|255] ""  SBMU

BO_ 2148761511 M2S_CMD3__23: 8 MBMU
 SG_ M2S_CMD3_TankNo_23 : 0|8@1+ (1,0) [0|255] ""  SBMU
 SG_ M2S_CMD3_KcFactor_23 : 8|16@1+ (1024,0) [0|67107840] ""  SBMU
 SG_ M2S_CMD3_KdFactor_23 : 24|16@1+ (1024,0) [0|67107840] ""  SBMU
 SG_ M2S_CMD3_TankSOC_23 : 40|16@1+ (0.1,0) [0|100] "%"  SBMU
 SG_ M2S_CMD3_SOCCmd_23 : 56|8@1+ (1,0) [0|255] ""  SBMU

BO_ 2148761512 M2S_CMD3__24: 8 MBMU
 SG_ M2S_CMD3_TankNo_24 : 0|8@1+ (1,0) [0|255] ""  SBMU
 SG_ M2S_CMD3_KcFactor_24 : 8|16@1+ (1024,0) [0|67107840] ""  SBMU
 SG_ M2S_CMD3_KdFactor_24 : 24|16@1+ (1024,0) [0|67107840] ""  SBMU
 SG_ M2S_CMD3_TankSOC_24 : 40|16@1+ (0.1,0) [0|100] "%"  SBMU
 SG_ M2S_CMD3_SOCCmd_24 : 56|8@1+ (1,0) [0|255] ""  SBMU

BO_ 2148761513 M2S_CMD3__25: 8 MBMU
 SG_ M2S_CMD3_TankNo_25 : 0|8@1+ (1,0) [0|255] ""  SBMU
 SG_ M2S_CMD3_KcFactor_25 : 8|16@1+ (1024,0) [0|67107840] ""  SBMU
 SG_ M2S_CMD3_KdFactor_25 : 24|16@1+ (1024,0) [0|67107840] ""  SBMU
 SG_ M2S_CMD3_TankSOC_25 : 40|16@1+ (0.1,0) [0|100] "%"  SBMU
 SG_ M2S_CMD3_SOCCmd_25 : 56|8@1+ (1,0) [0|255] ""  SBMU

BO_ 2148761514 M2S_CMD3__26: 8 MBMU
 SG_ M2S_CMD3_TankNo_26 : 0|8@1+ (1,0) [0|255] ""  SBMU
 SG_ M2S_CMD3_KcFactor_26 : 8|16@1+ (1024,0) [0|67107840] ""  SBMU
 SG_ M2S_CMD3_KdFactor_26 : 24|16@1+ (1024,0) [0|67107840] ""  SBMU
 SG_ M2S_CMD3_TankSOC_26 : 40|16@1+ (0.1,0) [0|100] "%"  SBMU
 SG_ M2S_CMD3_SOCCmd_26 : 56|8@1+ (1,0) [0|255] ""  SBMU

BO_ 2148761515 M2S_CMD3__27: 8 MBMU
 SG_ M2S_CMD3_TankNo_27 : 0|8@1+ (1,0) [0|255] ""  SBMU
 SG_ M2S_CMD3_KcFactor_27 : 8|16@1+ (1024,0) [0|67107840] ""  SBMU
 SG_ M2S_CMD3_KdFactor_27 : 24|16@1+ (1024,0) [0|67107840] ""  SBMU
 SG_ M2S_CMD3_TankSOC_27 : 40|16@1+ (0.1,0) [0|100] "%"  SBMU
 SG_ M2S_CMD3_SOCCmd_27 : 56|8@1+ (1,0) [0|255] ""  SBMU

BO_ 2148761516 M2S_CMD3__28: 8 MBMU
 SG_ M2S_CMD3_TankNo_28 : 0|8@1+ (1,0) [0|255] ""  SBMU
 SG_ M2S_CMD3_KcFactor_28 : 8|16@1+ (1024,0) [0|67107840] ""  SBMU
 SG_ M2S_CMD3_KdFactor_28 : 24|16@1+ (1024,0) [0|67107840] ""  SBMU
 SG_ M2S_CMD3_TankSOC_28 : 40|16@1+ (0.1,0) [0|100] "%"  SBMU
 SG_ M2S_CMD3_SOCCmd_28 : 56|8@1+ (1,0) [0|255] ""  SBMU

BO_ 2148761517 M2S_CMD3__29: 8 MBMU
 SG_ M2S_CMD3_TankNo_29 : 0|8@1+ (1,0) [0|255] ""  SBMU
 SG_ M2S_CMD3_KcFactor_29 : 8|16@1+ (1024,0) [0|67107840] ""  SBMU
 SG_ M2S_CMD3_KdFactor_29 : 24|16@1+ (1024,0) [0|67107840] ""  SBMU
 SG_ M2S_CMD3_TankSOC_29 : 40|16@1+ (0.1,0) [0|100] "%"  SBMU
 SG_ M2S_CMD3_SOCCmd_29 : 56|8@1+ (1,0) [0|255] ""  SBMU

BO_ 2148761518 M2S_CMD3__30: 8 MBMU
 SG_ M2S_CMD3_TankNo_30 : 0|8@1+ (1,0) [0|255] ""  SBMU
 SG_ M2S_CMD3_KcFactor_30 : 8|16@1+ (1024,0) [0|67107840] ""  SBMU
 SG_ M2S_CMD3_KdFactor_30 : 24|16@1+ (1024,0) [0|67107840] ""  SBMU
 SG_ M2S_CMD3_TankSOC_30 : 40|16@1+ (0.1,0) [0|100] "%"  SBMU
 SG_ M2S_CMD3_SOCCmd_30 : 56|8@1+ (1,0) [0|255] ""  SBMU

BO_ 2148761519 M2S_CMD3__31: 8 MBMU
 SG_ M2S_CMD3_TankNo_31 : 0|8@1+ (1,0) [0|255] ""  SBMU
 SG_ M2S_CMD3_KcFactor_31 : 8|16@1+ (1024,0) [0|67107840] ""  SBMU
 SG_ M2S_CMD3_KdFactor_31 : 24|16@1+ (1024,0) [0|67107840] ""  SBMU
 SG_ M2S_CMD3_TankSOC_31 : 40|16@1+ (0.1,0) [0|100] "%"  SBMU
 SG_ M2S_CMD3_SOCCmd_31 : 56|8@1+ (1,0) [0|255] ""  SBMU

BO_ 2265050769 M2P_Alarm__01: 8 MBMU
 SG_ M2P_AL_Fault_Page_01 : 0|8@1+ (1,0) [0|255] ""  PC
 SG_ M2P_AL_Fault_Number1_01 : 8|9@1+ (1,0) [0|511] ""  PC
 SG_ M2P_AL_Fault_Number2_01 : 17|9@1+ (1,0) [0|511] ""  PC
 SG_ M2P_AL_Fault_Number3_01 : 26|9@1+ (1,0) [0|511] ""  PC
 SG_ M2P_AL_Fault_Number4_01 : 35|9@1+ (1,0) [0|511] ""  PC
 SG_ M2P_AL_Fault_Number5_01 : 44|9@1+ (1,0) [0|511] ""  PC
 SG_ M2P_AL_Fault_Number6_01 : 53|9@1+ (1,0) [0|511] ""  PC

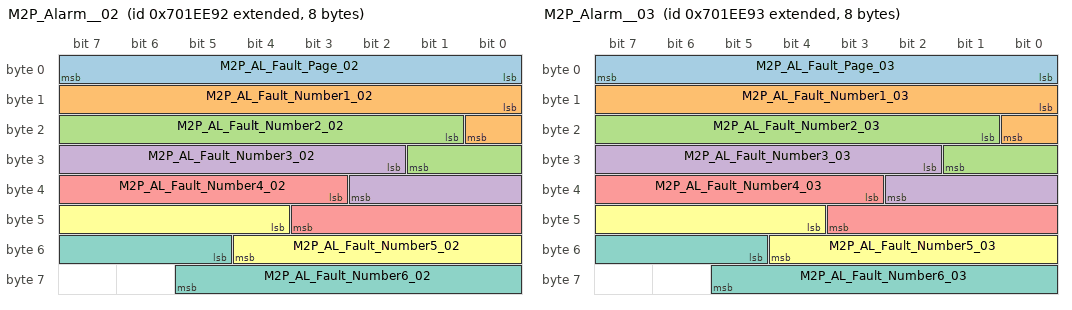
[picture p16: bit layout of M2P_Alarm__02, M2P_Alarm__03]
BO_ 2265050770 M2P_Alarm__02: 8 MBMU
 SG_ M2P_AL_Fault_Page_02 : 0|8@1+ (1,0) [0|255] ""  PC
 SG_ M2P_AL_Fault_Number1_02 : 8|9@1+ (1,0) [0|511] ""  PC
 SG_ M2P_AL_Fault_Number2_02 : 17|9@1+ (1,0) [0|511] ""  PC
 SG_ M2P_AL_Fault_Number3_02 : 26|9@1+ (1,0) [0|511] ""  PC
 SG_ M2P_AL_Fault_Number4_02 : 35|9@1+ (1,0) [0|511] ""  PC
 SG_ M2P_AL_Fault_Number5_02 : 44|9@1+ (1,0) [0|511] ""  PC
 SG_ M2P_AL_Fault_Number6_02 : 53|9@1+ (1,0) [0|511] ""  PC

BO_ 2265050771 M2P_Alarm__03: 8 MBMU
 SG_ M2P_AL_Fault_Page_03 : 0|8@1+ (1,0) [0|255] ""  PC
 SG_ M2P_AL_Fault_Number1_03 : 8|9@1+ (1,0) [0|511] ""  PC
 SG_ M2P_AL_Fault_Number2_03 : 17|9@1+ (1,0) [0|511] ""  PC
 SG_ M2P_AL_Fault_Number3_03 : 26|9@1+ (1,0) [0|511] ""  PC
 SG_ M2P_AL_Fault_Number4_03 : 35|9@1+ (1,0) [0|511] ""  PC
 SG_ M2P_AL_Fault_Number5_03 : 44|9@1+ (1,0) [0|511] ""  PC
 SG_ M2P_AL_Fault_Number6_03 : 53|9@1+ (1,0) [0|511] ""  PC

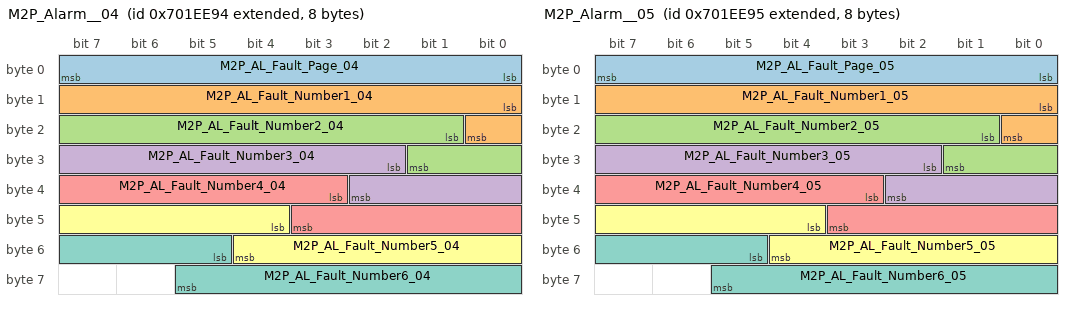
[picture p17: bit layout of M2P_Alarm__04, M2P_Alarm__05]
BO_ 2265050772 M2P_Alarm__04: 8 MBMU
 SG_ M2P_AL_Fault_Page_04 : 0|8@1+ (1,0) [0|255] ""  PC
 SG_ M2P_AL_Fault_Number1_04 : 8|9@1+ (1,0) [0|511] ""  PC
 SG_ M2P_AL_Fault_Number2_04 : 17|9@1+ (1,0) [0|511] ""  PC
 SG_ M2P_AL_Fault_Number3_04 : 26|9@1+ (1,0) [0|511] ""  PC
 SG_ M2P_AL_Fault_Number4_04 : 35|9@1+ (1,0) [0|511] ""  PC
 SG_ M2P_AL_Fault_Number5_04 : 44|9@1+ (1,0) [0|511] ""  PC
 SG_ M2P_AL_Fault_Number6_04 : 53|9@1+ (1,0) [0|511] ""  PC

BO_ 2265050773 M2P_Alarm__05: 8 MBMU
 SG_ M2P_AL_Fault_Page_05 : 0|8@1+ (1,0) [0|255] ""  PC
 SG_ M2P_AL_Fault_Number1_05 : 8|9@1+ (1,0) [0|511] ""  PC
 SG_ M2P_AL_Fault_Number2_05 : 17|9@1+ (1,0) [0|511] ""  PC
 SG_ M2P_AL_Fault_Number3_05 : 26|9@1+ (1,0) [0|511] ""  PC
 SG_ M2P_AL_Fault_Number4_05 : 35|9@1+ (1,0) [0|511] ""  PC
 SG_ M2P_AL_Fault_Number5_05 : 44|9@1+ (1,0) [0|511] ""  PC
 SG_ M2P_AL_Fault_Number6_05 : 53|9@1+ (1,0) [0|511] ""  PC

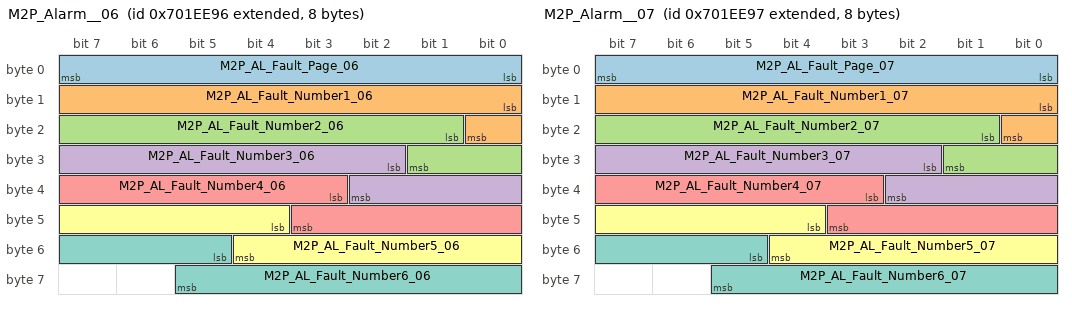
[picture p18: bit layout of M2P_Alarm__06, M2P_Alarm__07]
BO_ 2265050774 M2P_Alarm__06: 8 MBMU
 SG_ M2P_AL_Fault_Page_06 : 0|8@1+ (1,0) [0|255] ""  PC
 SG_ M2P_AL_Fault_Number1_06 : 8|9@1+ (1,0) [0|511] ""  PC
 SG_ M2P_AL_Fault_Number2_06 : 17|9@1+ (1,0) [0|511] ""  PC
 SG_ M2P_AL_Fault_Number3_06 : 26|9@1+ (1,0) [0|511] ""  PC
 SG_ M2P_AL_Fault_Number4_06 : 35|9@1+ (1,0) [0|511] ""  PC
 SG_ M2P_AL_Fault_Number5_06 : 44|9@1+ (1,0) [0|511] ""  PC
 SG_ M2P_AL_Fault_Number6_06 : 53|9@1+ (1,0) [0|511] ""  PC

BO_ 2265050775 M2P_Alarm__07: 8 MBMU
 SG_ M2P_AL_Fault_Page_07 : 0|8@1+ (1,0) [0|255] ""  PC
 SG_ M2P_AL_Fault_Number1_07 : 8|9@1+ (1,0) [0|511] ""  PC
 SG_ M2P_AL_Fault_Number2_07 : 17|9@1+ (1,0) [0|511] ""  PC
 SG_ M2P_AL_Fault_Number3_07 : 26|9@1+ (1,0) [0|511] ""  PC
 SG_ M2P_AL_Fault_Number4_07 : 35|9@1+ (1,0) [0|511] ""  PC
 SG_ M2P_AL_Fault_Number5_07 : 44|9@1+ (1,0) [0|511] ""  PC
 SG_ M2P_AL_Fault_Number6_07 : 53|9@1+ (1,0) [0|511] ""  PC

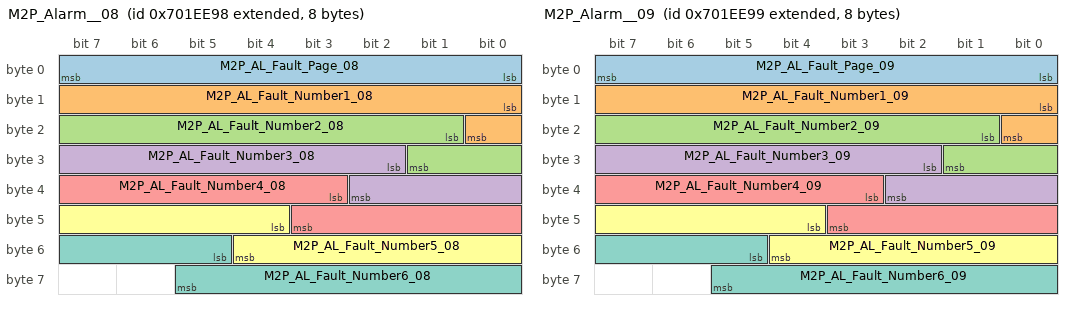
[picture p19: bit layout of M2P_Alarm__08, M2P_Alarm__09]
BO_ 2265050776 M2P_Alarm__08: 8 MBMU
 SG_ M2P_AL_Fault_Page_08 : 0|8@1+ (1,0) [0|255] ""  PC
 SG_ M2P_AL_Fault_Number1_08 : 8|9@1+ (1,0) [0|511] ""  PC
 SG_ M2P_AL_Fault_Number2_08 : 17|9@1+ (1,0) [0|511] ""  PC
 SG_ M2P_AL_Fault_Number3_08 : 26|9@1+ (1,0) [0|511] ""  PC
 SG_ M2P_AL_Fault_Number4_08 : 35|9@1+ (1,0) [0|511] ""  PC
 SG_ M2P_AL_Fault_Number5_08 : 44|9@1+ (1,0) [0|511] ""  PC
 SG_ M2P_AL_Fault_Number6_08 : 53|9@1+ (1,0) [0|511] ""  PC

BO_ 2265050777 M2P_Alarm__09: 8 MBMU
 SG_ M2P_AL_Fault_Page_09 : 0|8@1+ (1,0) [0|255] ""  PC
 SG_ M2P_AL_Fault_Number1_09 : 8|9@1+ (1,0) [0|511] ""  PC
 SG_ M2P_AL_Fault_Number2_09 : 17|9@1+ (1,0) [0|511] ""  PC
 SG_ M2P_AL_Fault_Number3_09 : 26|9@1+ (1,0) [0|511] ""  PC
 SG_ M2P_AL_Fault_Number4_09 : 35|9@1+ (1,0) [0|511] ""  PC
 SG_ M2P_AL_Fault_Number5_09 : 44|9@1+ (1,0) [0|511] ""  PC
 SG_ M2P_AL_Fault_Number6_09 : 53|9@1+ (1,0) [0|511] ""  PC

BO_ 2265050778 M2P_Alarm__10: 8 MBMU
 SG_ M2P_AL_Fault_Page_10 : 0|8@1+ (1,0) [0|255] ""  PC
 SG_ M2P_AL_Fault_Number1_10 : 8|9@1+ (1,0) [0|511] ""  PC
 SG_ M2P_AL_Fault_Number2_10 : 17|9@1+ (1,0) [0|511] ""  PC
 SG_ M2P_AL_Fault_Number3_10 : 26|9@1+ (1,0) [0|511] ""  PC
 SG_ M2P_AL_Fault_Number4_10 : 35|9@1+ (1,0) [0|511] ""  PC
 SG_ M2P_AL_Fault_Number5_10 : 44|9@1+ (1,0) [0|511] ""  PC
 SG_ M2P_AL_Fault_Number6_10 : 53|9@1+ (1,0) [0|511] ""  PC

BO_ 2265050779 M2P_Alarm__11: 8 MBMU
 SG_ M2P_AL_Fault_Page_11 : 0|8@1+ (1,0) [0|255] ""  PC
 SG_ M2P_AL_Fault_Number1_11 : 8|9@1+ (1,0) [0|511] ""  PC
 SG_ M2P_AL_Fault_Number2_11 : 17|9@1+ (1,0) [0|511] ""  PC
 SG_ M2P_AL_Fault_Number3_11 : 26|9@1+ (1,0) [0|511] ""  PC
 SG_ M2P_AL_Fault_Number4_11 : 35|9@1+ (1,0) [0|511] ""  PC
 SG_ M2P_AL_Fault_Number5_11 : 44|9@1+ (1,0) [0|511] ""  PC
 SG_ M2P_AL_Fault_Number6_11 : 53|9@1+ (1,0) [0|511] ""  PC

BO_ 2265050780 M2P_Alarm__12: 8 MBMU
 SG_ M2P_AL_Fault_Page_12 : 0|8@1+ (1,0) [0|255] ""  PC
 SG_ M2P_AL_Fault_Number1_12 : 8|9@1+ (1,0) [0|511] ""  PC
 SG_ M2P_AL_Fault_Number2_12 : 17|9@1+ (1,0) [0|511] ""  PC
 SG_ M2P_AL_Fault_Number3_12 : 26|9@1+ (1,0) [0|511] ""  PC
 SG_ M2P_AL_Fault_Number4_12 : 35|9@1+ (1,0) [0|511] ""  PC
 SG_ M2P_AL_Fault_Number5_12 : 44|9@1+ (1,0) [0|511] ""  PC
 SG_ M2P_AL_Fault_Number6_12 : 53|9@1+ (1,0) [0|511] ""  PC

CM_ SG_ 2148630433 HvPwrOnCmd_SBMU01_17 "高压控制指令";
CM_ SG_ 2148630433 HvPwrOnCmd_SBMU02_17 "高压控制指令";
CM_ SG_ 2148630433 HvPwrOnCmd_SBMU03_17 "高压控制指令";
CM_ SG_ 2148630433 HvPwrOnCmd_SBMU04_17 "高压控制指令";
CM_ SG_ 2148630433 HvPwrOnCmd_SBMU05_17 "高压控制指令";
CM_ SG_ 2148630433 HvPwrOnCmd_SBMU06_17 "高压控制指令";
CM_ SG_ 2148630433 HvPwrOnCmd_SBMU07_17 "高压控制指令";
CM_ SG_ 2148630433 HvPwrOnCmd_SBMU08_17 "高压控制指令";
CM_ SG_ 2148630433 HvPwrOnCmd_SBMU09_17 "高压控制指令";
CM_ SG_ 2148630433 HvPwrOnCmd_SBMU10_17 "高压控制指令";
CM_ SG_ 2148630433 HvPwrOnCmd_SBMU11_17 "高压控制指令";
CM_ SG_ 2148630433 HvPwrOnCmd_SBMU12_17 "高压控制指令";
CM_ SG_ 2148630433 HvPwrOnCmd_SBMU13_17 "高压控制指令";
CM_ SG_ 2148630433 HvPwrOnCmd_SBMU14_17 "高压控制指令";
CM_ SG_ 2148630433 HvPwrOnCmd_SBMU15_17 "高压控制指令";
CM_ SG_ 2148630433 HvPwrOnCmd_SBMU16_17 "高压控制指令";
CM_ SG_ 2148630433 HvPwrOnCmd_SBMU17_17 "高压控制指令";
CM_ SG_ 2148630433 HvPwrOnCmd_SBMU18_17 "高压控制指令";
CM_ SG_ 2148630433 HvPwrOnCmd_SBMU19_17 "高压控制指令";
CM_ SG_ 2148630433 HvPwrOnCmd_SBMU20_17 "高压控制指令";
CM_ SG_ 2148630433 HvPwrOnCmd_SBMU21_17 "高压控制指令";
CM_ SG_ 2148630433 HvPwrOnCmd_SBMU22_17 "高压控制指令";
CM_ SG_ 2148630433 HvPwrOnCmd_SBMU23_17 "高压控制指令";
CM_ SG_ 2148630433 HvPwrOnCmd_SBMU24_17 "高压控制指令";
CM_ SG_ 2148630433 HvPwrOnCmd_SBMU25_17 "高压控制指令";
CM_ SG_ 2148630433 HvPwrOnCmd_SBMU26_17 "高压控制指令";
CM_ SG_ 2148630433 HvPwrOnCmd_SBMU27_17 "高压控制指令";
CM_ SG_ 2148630433 HvPwrOnCmd_SBMU28_17 "高压控制指令";
CM_ SG_ 2148630433 HvPwrOnCmd_SBMU29_17 "高压控制指令";
CM_ SG_ 2148630433 HvPwrOnCmd_SBMU30_17 "高压控制指令";
CM_ SG_ 2148630433 HvPwrOnCmd_SBMU31_17 "高压控制指令";
CM_ SG_ 2148630433 HvPwrOnCmd_SBMU32_17 "高压控制指令";
CM_ SG_ 2148630434 HvPwrOnCmd_SBMU01_18 "高压控制指令";
CM_ SG_ 2148630434 HvPwrOnCmd_SBMU02_18 "高压控制指令";
CM_ SG_ 2148630434 HvPwrOnCmd_SBMU03_18 "高压控制指令";
CM_ SG_ 2148630434 HvPwrOnCmd_SBMU04_18 "高压控制指令";
CM_ SG_ 2148630434 HvPwrOnCmd_SBMU05_18 "高压控制指令";
CM_ SG_ 2148630434 HvPwrOnCmd_SBMU06_18 "高压控制指令";
CM_ SG_ 2148630434 HvPwrOnCmd_SBMU07_18 "高压控制指令";
CM_ SG_ 2148630434 HvPwrOnCmd_SBMU08_18 "高压控制指令";
CM_ SG_ 2148630434 HvPwrOnCmd_SBMU09_18 "高压控制指令";
CM_ SG_ 2148630434 HvPwrOnCmd_SBMU10_18 "高压控制指令";
CM_ SG_ 2148630434 HvPwrOnCmd_SBMU11_18 "高压控制指令";
CM_ SG_ 2148630434 HvPwrOnCmd_SBMU12_18 "高压控制指令";
CM_ SG_ 2148630434 HvPwrOnCmd_SBMU13_18 "高压控制指令";
CM_ SG_ 2148630434 HvPwrOnCmd_SBMU14_18 "高压控制指令";
CM_ SG_ 2148630434 HvPwrOnCmd_SBMU15_18 "高压控制指令";
CM_ SG_ 2148630434 HvPwrOnCmd_SBMU16_18 "高压控制指令";
CM_ SG_ 2148630434 HvPwrOnCmd_SBMU17_18 "高压控制指令";
CM_ SG_ 2148630434 HvPwrOnCmd_SBMU18_18 "高压控制指令";
CM_ SG_ 2148630434 HvPwrOnCmd_SBMU19_18 "高压控制指令";
CM_ SG_ 2148630434 HvPwrOnCmd_SBMU20_18 "高压控制指令";
CM_ SG_ 2148630434 HvPwrOnCmd_SBMU21_18 "高压控制指令";
CM_ SG_ 2148630434 HvPwrOnCmd_SBMU22_18 "高压控制指令";
CM_ SG_ 2148630434 HvPwrOnCmd_SBMU23_18 "高压控制指令";
CM_ SG_ 2148630434 HvPwrOnCmd_SBMU24_18 "高压控制指令";
CM_ SG_ 2148630434 HvPwrOnCmd_SBMU25_18 "高压控制指令";
CM_ SG_ 2148630434 HvPwrOnCmd_SBMU26_18 "高压控制指令";
CM_ SG_ 2148630434 HvPwrOnCmd_SBMU27_18 "高压控制指令";
CM_ SG_ 2148630434 HvPwrOnCmd_SBMU28_18 "高压控制指令";
CM_ SG_ 2148630434 HvPwrOnCmd_SBMU29_18 "高压控制指令";
CM_ SG_ 2148630434 HvPwrOnCmd_SBMU30_18 "高压控制指令";
CM_ SG_ 2148630434 HvPwrOnCmd_SBMU31_18 "高压控制指令";
CM_ SG_ 2148630434 HvPwrOnCmd_SBMU32_18 "高压控制指令";
CM_ SG_ 2148630435 HvPwrOnCmd_SBMU01_19 "高压控制指令";
CM_ SG_ 2148630435 HvPwrOnCmd_SBMU02_19 "高压控制指令";
CM_ SG_ 2148630435 HvPwrOnCmd_SBMU03_19 "高压控制指令";
CM_ SG_ 2148630435 HvPwrOnCmd_SBMU04_19 "高压控制指令";
CM_ SG_ 2148630435 HvPwrOnCmd_SBMU05_19 "高压控制指令";
CM_ SG_ 2148630435 HvPwrOnCmd_SBMU06_19 "高压控制指令";
CM_ SG_ 2148630435 HvPwrOnCmd_SBMU07_19 "高压控制指令";
CM_ SG_ 2148630435 HvPwrOnCmd_SBMU08_19 "高压控制指令";
CM_ SG_ 2148630435 HvPwrOnCmd_SBMU09_19 "高压控制指令";
CM_ SG_ 2148630435 HvPwrOnCmd_SBMU10_19 "高压控制指令";
CM_ SG_ 2148630435 HvPwrOnCmd_SBMU11_19 "高压控制指令";
CM_ SG_ 2148630435 HvPwrOnCmd_SBMU12_19 "高压控制指令";
CM_ SG_ 2148630435 HvPwrOnCmd_SBMU13_19 "高压控制指令";
CM_ SG_ 2148630435 HvPwrOnCmd_SBMU14_19 "高压控制指令";
CM_ SG_ 2148630435 HvPwrOnCmd_SBMU15_19 "高压控制指令";
CM_ SG_ 2148630435 HvPwrOnCmd_SBMU16_19 "高压控制指令";
CM_ SG_ 2148630435 HvPwrOnCmd_SBMU17_19 "高压控制指令";
CM_ SG_ 2148630435 HvPwrOnCmd_SBMU18_19 "高压控制指令";
CM_ SG_ 2148630435 HvPwrOnCmd_SBMU19_19 "高压控制指令";
CM_ SG_ 2148630435 HvPwrOnCmd_SBMU20_19 "高压控制指令";
CM_ SG_ 2148630435 HvPwrOnCmd_SBMU21_19 "高压控制指令";
CM_ SG_ 2148630435 HvPwrOnCmd_SBMU22_19 "高压控制指令";
CM_ SG_ 2148630435 HvPwrOnCmd_SBMU23_19 "高压控制指令";
CM_ SG_ 2148630435 HvPwrOnCmd_SBMU24_19 "高压控制指令";
CM_ SG_ 2148630435 HvPwrOnCmd_SBMU25_19 "高压控制指令";
CM_ SG_ 2148630435 HvPwrOnCmd_SBMU26_19 "高压控制指令";
CM_ SG_ 2148630435 HvPwrOnCmd_SBMU27_19 "高压控制指令";
CM_ SG_ 2148630435 HvPwrOnCmd_SBMU28_19 "高压控制指令";
CM_ SG_ 2148630435 HvPwrOnCmd_SBMU29_19 "高压控制指令";
CM_ SG_ 2148630435 HvPwrOnCmd_SBMU30_19 "高压控制指令";
CM_ SG_ 2148630435 HvPwrOnCmd_SBMU31_19 "高压控制指令";
CM_ SG_ 2148630435 HvPwrOnCmd_SBMU32_19 "高压控制指令";
CM_ SG_ 2148630436 HvPwrOnCmd_SBMU01_20 "高压控制指令";
CM_ SG_ 2148630436 HvPwrOnCmd_SBMU02_20 "高压控制指令";
CM_ SG_ 2148630436 HvPwrOnCmd_SBMU03_20 "高压控制指令";
CM_ SG_ 2148630436 HvPwrOnCmd_SBMU04_20 "高压控制指令";
CM_ SG_ 2148630436 HvPwrOnCmd_SBMU05_20 "高压控制指令";
CM_ SG_ 2148630436 HvPwrOnCmd_SBMU06_20 "高压控制指令";
CM_ SG_ 2148630436 HvPwrOnCmd_SBMU07_20 "高压控制指令";
CM_ SG_ 2148630436 HvPwrOnCmd_SBMU08_20 "高压控制指令";
CM_ SG_ 2148630436 HvPwrOnCmd_SBMU09_20 "高压控制指令";
CM_ SG_ 2148630436 HvPwrOnCmd_SBMU10_20 "高压控制指令";
CM_ SG_ 2148630436 HvPwrOnCmd_SBMU11_20 "高压控制指令";
CM_ SG_ 2148630436 HvPwrOnCmd_SBMU12_20 "高压控制指令";
CM_ SG_ 2148630436 HvPwrOnCmd_SBMU13_20 "高压控制指令";
CM_ SG_ 2148630436 HvPwrOnCmd_SBMU14_20 "高压控制指令";
CM_ SG_ 2148630436 HvPwrOnCmd_SBMU15_20 "高压控制指令";
CM_ SG_ 2148630436 HvPwrOnCmd_SBMU16_20 "高压控制指令";
CM_ SG_ 2148630436 HvPwrOnCmd_SBMU17_20 "高压控制指令";
CM_ SG_ 2148630436 HvPwrOnCmd_SBMU18_20 "高压控制指令";
CM_ SG_ 2148630436 HvPwrOnCmd_SBMU19_20 "高压控制指令";
CM_ SG_ 2148630436 HvPwrOnCmd_SBMU20_20 "高压控制指令";
CM_ SG_ 2148630436 HvPwrOnCmd_SBMU21_20 "高压控制指令";
CM_ SG_ 2148630436 HvPwrOnCmd_SBMU22_20 "高压控制指令";
CM_ SG_ 2148630436 HvPwrOnCmd_SBMU23_20 "高压控制指令";
CM_ SG_ 2148630436 HvPwrOnCmd_SBMU24_20 "高压控制指令";
CM_ SG_ 2148630436 HvPwrOnCmd_SBMU25_20 "高压控制指令";
CM_ SG_ 2148630436 HvPwrOnCmd_SBMU26_20 "高压控制指令";
CM_ SG_ 2148630436 HvPwrOnCmd_SBMU27_20 "高压控制指令";
CM_ SG_ 2148630436 HvPwrOnCmd_SBMU28_20 "高压控制指令";
CM_ SG_ 2148630436 HvPwrOnCmd_SBMU29_20 "高压控制指令";
CM_ SG_ 2148630436 HvPwrOnCmd_SBMU30_20 "高压控制指令";
CM_ SG_ 2148630436 HvPwrOnCmd_SBMU31_20 "高压控制指令";
CM_ SG_ 2148630436 HvPwrOnCmd_SBMU32_20 "高压控制指令";
CM_ SG_ 2148630437 HvPwrOnCmd_SBMU01_21 "高压控制指令";
CM_ SG_ 2148630437 HvPwrOnCmd_SBMU02_21 "高压控制指令";
CM_ SG_ 2148630437 HvPwrOnCmd_SBMU03_21 "高压控制指令";
CM_ SG_ 2148630437 HvPwrOnCmd_SBMU04_21 "高压控制指令";
CM_ SG_ 2148630437 HvPwrOnCmd_SBMU05_21 "高压控制指令";
CM_ SG_ 2148630437 HvPwrOnCmd_SBMU06_21 "高压控制指令";
CM_ SG_ 2148630437 HvPwrOnCmd_SBMU07_21 "高压控制指令";
CM_ SG_ 2148630437 HvPwrOnCmd_SBMU08_21 "高压控制指令";
CM_ SG_ 2148630437 HvPwrOnCmd_SBMU09_21 "高压控制指令";
CM_ SG_ 2148630437 HvPwrOnCmd_SBMU10_21 "高压控制指令";
CM_ SG_ 2148630437 HvPwrOnCmd_SBMU11_21 "高压控制指令";
CM_ SG_ 2148630437 HvPwrOnCmd_SBMU12_21 "高压控制指令";
CM_ SG_ 2148630437 HvPwrOnCmd_SBMU13_21 "高压控制指令";
CM_ SG_ 2148630437 HvPwrOnCmd_SBMU14_21 "高压控制指令";
CM_ SG_ 2148630437 HvPwrOnCmd_SBMU15_21 "高压控制指令";
CM_ SG_ 2148630437 HvPwrOnCmd_SBMU16_21 "高压控制指令";
CM_ SG_ 2148630437 HvPwrOnCmd_SBMU17_21 "高压控制指令";
CM_ SG_ 2148630437 HvPwrOnCmd_SBMU18_21 "高压控制指令";
CM_ SG_ 2148630437 HvPwrOnCmd_SBMU19_21 "高压控制指令";
CM_ SG_ 2148630437 HvPwrOnCmd_SBMU20_21 "高压控制指令";
CM_ SG_ 2148630437 HvPwrOnCmd_SBMU21_21 "高压控制指令";
CM_ SG_ 2148630437 HvPwrOnCmd_SBMU22_21 "高压控制指令";
CM_ SG_ 2148630437 HvPwrOnCmd_SBMU23_21 "高压控制指令";
CM_ SG_ 2148630437 HvPwrOnCmd_SBMU24_21 "高压控制指令";
CM_ SG_ 2148630437 HvPwrOnCmd_SBMU25_21 "高压控制指令";
CM_ SG_ 2148630437 HvPwrOnCmd_SBMU26_21 "高压控制指令";
CM_ SG_ 2148630437 HvPwrOnCmd_SBMU27_21 "高压控制指令";
CM_ SG_ 2148630437 HvPwrOnCmd_SBMU28_21 "高压控制指令";
CM_ SG_ 2148630437 HvPwrOnCmd_SBMU29_21 "高压控制指令";
CM_ SG_ 2148630437 HvPwrOnCmd_SBMU30_21 "高压控制指令";
CM_ SG_ 2148630437 HvPwrOnCmd_SBMU31_21 "高压控制指令";
CM_ SG_ 2148630437 HvPwrOnCmd_SBMU32_21 "高压控制指令";
CM_ SG_ 2148630438 HvPwrOnCmd_SBMU01_22 "高压控制指令";
CM_ SG_ 2148630438 HvPwrOnCmd_SBMU02_22 "高压控制指令";
CM_ SG_ 2148630438 HvPwrOnCmd_SBMU03_22 "高压控制指令";
CM_ SG_ 2148630438 HvPwrOnCmd_SBMU04_22 "高压控制指令";
CM_ SG_ 2148630438 HvPwrOnCmd_SBMU05_22 "高压控制指令";
CM_ SG_ 2148630438 HvPwrOnCmd_SBMU06_22 "高压控制指令";
CM_ SG_ 2148630438 HvPwrOnCmd_SBMU07_22 "高压控制指令";
CM_ SG_ 2148630438 HvPwrOnCmd_SBMU08_22 "高压控制指令";
CM_ SG_ 2148630438 HvPwrOnCmd_SBMU09_22 "高压控制指令";
CM_ SG_ 2148630438 HvPwrOnCmd_SBMU10_22 "高压控制指令";
CM_ SG_ 2148630438 HvPwrOnCmd_SBMU11_22 "高压控制指令";
CM_ SG_ 2148630438 HvPwrOnCmd_SBMU12_22 "高压控制指令";
CM_ SG_ 2148630438 HvPwrOnCmd_SBMU13_22 "高压控制指令";
CM_ SG_ 2148630438 HvPwrOnCmd_SBMU14_22 "高压控制指令";
CM_ SG_ 2148630438 HvPwrOnCmd_SBMU15_22 "高压控制指令";
CM_ SG_ 2148630438 HvPwrOnCmd_SBMU16_22 "高压控制指令";
CM_ SG_ 2148630438 HvPwrOnCmd_SBMU17_22 "高压控制指令";
CM_ SG_ 2148630438 HvPwrOnCmd_SBMU18_22 "高压控制指令";
CM_ SG_ 2148630438 HvPwrOnCmd_SBMU19_22 "高压控制指令";
CM_ SG_ 2148630438 HvPwrOnCmd_SBMU20_22 "高压控制指令";
CM_ SG_ 2148630438 HvPwrOnCmd_SBMU21_22 "高压控制指令";
CM_ SG_ 2148630438 HvPwrOnCmd_SBMU22_22 "高压控制指令";
CM_ SG_ 2148630438 HvPwrOnCmd_SBMU23_22 "高压控制指令";
CM_ SG_ 2148630438 HvPwrOnCmd_SBMU24_22 "高压控制指令";
CM_ SG_ 2148630438 HvPwrOnCmd_SBMU25_22 "高压控制指令";
CM_ SG_ 2148630438 HvPwrOnCmd_SBMU26_22 "高压控制指令";
CM_ SG_ 2148630438 HvPwrOnCmd_SBMU27_22 "高压控制指令";
CM_ SG_ 2148630438 HvPwrOnCmd_SBMU28_22 "高压控制指令";
CM_ SG_ 2148630438 HvPwrOnCmd_SBMU29_22 "高压控制指令";
CM_ SG_ 2148630438 HvPwrOnCmd_SBMU30_22 "高压控制指令";
CM_ SG_ 2148630438 HvPwrOnCmd_SBMU31_22 "高压控制指令";
CM_ SG_ 2148630438 HvPwrOnCmd_SBMU32_22 "高压控制指令";
CM_ SG_ 2148630439 HvPwrOnCmd_SBMU01_23 "高压控制指令";
CM_ SG_ 2148630439 HvPwrOnCmd_SBMU02_23 "高压控制指令";
CM_ SG_ 2148630439 HvPwrOnCmd_SBMU03_23 "高压控制指令";
CM_ SG_ 2148630439 HvPwrOnCmd_SBMU04_23 "高压控制指令";
CM_ SG_ 2148630439 HvPwrOnCmd_SBMU05_23 "高压控制指令";
CM_ SG_ 2148630439 HvPwrOnCmd_SBMU06_23 "高压控制指令";
CM_ SG_ 2148630439 HvPwrOnCmd_SBMU07_23 "高压控制指令";
CM_ SG_ 2148630439 HvPwrOnCmd_SBMU08_23 "高压控制指令";
CM_ SG_ 2148630439 HvPwrOnCmd_SBMU09_23 "高压控制指令";
CM_ SG_ 2148630439 HvPwrOnCmd_SBMU10_23 "高压控制指令";
CM_ SG_ 2148630439 HvPwrOnCmd_SBMU11_23 "高压控制指令";
CM_ SG_ 2148630439 HvPwrOnCmd_SBMU12_23 "高压控制指令";
CM_ SG_ 2148630439 HvPwrOnCmd_SBMU13_23 "高压控制指令";
CM_ SG_ 2148630439 HvPwrOnCmd_SBMU14_23 "高压控制指令";
CM_ SG_ 2148630439 HvPwrOnCmd_SBMU15_23 "高压控制指令";
CM_ SG_ 2148630439 HvPwrOnCmd_SBMU16_23 "高压控制指令";
CM_ SG_ 2148630439 HvPwrOnCmd_SBMU17_23 "高压控制指令";
CM_ SG_ 2148630439 HvPwrOnCmd_SBMU18_23 "高压控制指令";
CM_ SG_ 2148630439 HvPwrOnCmd_SBMU19_23 "高压控制指令";
CM_ SG_ 2148630439 HvPwrOnCmd_SBMU20_23 "高压控制指令";
CM_ SG_ 2148630439 HvPwrOnCmd_SBMU21_23 "高压控制指令";
CM_ SG_ 2148630439 HvPwrOnCmd_SBMU22_23 "高压控制指令";
CM_ SG_ 2148630439 HvPwrOnCmd_SBMU23_23 "高压控制指令";
CM_ SG_ 2148630439 HvPwrOnCmd_SBMU24_23 "高压控制指令";
CM_ SG_ 2148630439 HvPwrOnCmd_SBMU25_23 "高压控制指令";
CM_ SG_ 2148630439 HvPwrOnCmd_SBMU26_23 "高压控制指令";
CM_ SG_ 2148630439 HvPwrOnCmd_SBMU27_23 "高压控制指令";
CM_ SG_ 2148630439 HvPwrOnCmd_SBMU28_23 "高压控制指令";
CM_ SG_ 2148630439 HvPwrOnCmd_SBMU29_23 "高压控制指令";
CM_ SG_ 2148630439 HvPwrOnCmd_SBMU30_23 "高压控制指令";
CM_ SG_ 2148630439 HvPwrOnCmd_SBMU31_23 "高压控制指令";
CM_ SG_ 2148630439 HvPwrOnCmd_SBMU32_23 "高压控制指令";
CM_ SG_ 2148630440 HvPwrOnCmd_SBMU01_24 "高压控制指令";
CM_ SG_ 2148630440 HvPwrOnCmd_SBMU02_24 "高压控制指令";
CM_ SG_ 2148630440 HvPwrOnCmd_SBMU03_24 "高压控制指令";
CM_ SG_ 2148630440 HvPwrOnCmd_SBMU04_24 "高压控制指令";
CM_ SG_ 2148630440 HvPwrOnCmd_SBMU05_24 "高压控制指令";
CM_ SG_ 2148630440 HvPwrOnCmd_SBMU06_24 "高压控制指令";
CM_ SG_ 2148630440 HvPwrOnCmd_SBMU07_24 "高压控制指令";
CM_ SG_ 2148630440 HvPwrOnCmd_SBMU08_24 "高压控制指令";
CM_ SG_ 2148630440 HvPwrOnCmd_SBMU09_24 "高压控制指令";
CM_ SG_ 2148630440 HvPwrOnCmd_SBMU10_24 "高压控制指令";
CM_ SG_ 2148630440 HvPwrOnCmd_SBMU11_24 "高压控制指令";
CM_ SG_ 2148630440 HvPwrOnCmd_SBMU12_24 "高压控制指令";
CM_ SG_ 2148630440 HvPwrOnCmd_SBMU13_24 "高压控制指令";
CM_ SG_ 2148630440 HvPwrOnCmd_SBMU14_24 "高压控制指令";
CM_ SG_ 2148630440 HvPwrOnCmd_SBMU15_24 "高压控制指令";
CM_ SG_ 2148630440 HvPwrOnCmd_SBMU16_24 "高压控制指令";
CM_ SG_ 2148630440 HvPwrOnCmd_SBMU17_24 "高压控制指令";
CM_ SG_ 2148630440 HvPwrOnCmd_SBMU18_24 "高压控制指令";
CM_ SG_ 2148630440 HvPwrOnCmd_SBMU19_24 "高压控制指令";
CM_ SG_ 2148630440 HvPwrOnCmd_SBMU20_24 "高压控制指令";
CM_ SG_ 2148630440 HvPwrOnCmd_SBMU21_24 "高压控制指令";
CM_ SG_ 2148630440 HvPwrOnCmd_SBMU22_24 "高压控制指令";
CM_ SG_ 2148630440 HvPwrOnCmd_SBMU23_24 "高压控制指令";
CM_ SG_ 2148630440 HvPwrOnCmd_SBMU24_24 "高压控制指令";
CM_ SG_ 2148630440 HvPwrOnCmd_SBMU25_24 "高压控制指令";
CM_ SG_ 2148630440 HvPwrOnCmd_SBMU26_24 "高压控制指令";
CM_ SG_ 2148630440 HvPwrOnCmd_SBMU27_24 "高压控制指令";
CM_ SG_ 2148630440 HvPwrOnCmd_SBMU28_24 "高压控制指令";
CM_ SG_ 2148630440 HvPwrOnCmd_SBMU29_24 "高压控制指令";
CM_ SG_ 2148630440 HvPwrOnCmd_SBMU30_24 "高压控制指令";
CM_ SG_ 2148630440 HvPwrOnCmd_SBMU31_24 "高压控制指令";
CM_ SG_ 2148630440 HvPwrOnCmd_SBMU32_24 "高压控制指令";
CM_ SG_ 2148630441 HvPwrOnCmd_SBMU01_25 "高压控制指令";
CM_ SG_ 2148630441 HvPwrOnCmd_SBMU02_25 "高压控制指令";
CM_ SG_ 2148630441 HvPwrOnCmd_SBMU03_25 "高压控制指令";
CM_ SG_ 2148630441 HvPwrOnCmd_SBMU04_25 "高压控制指令";
CM_ SG_ 2148630441 HvPwrOnCmd_SBMU05_25 "高压控制指令";
CM_ SG_ 2148630441 HvPwrOnCmd_SBMU06_25 "高压控制指令";
CM_ SG_ 2148630441 HvPwrOnCmd_SBMU07_25 "高压控制指令";
CM_ SG_ 2148630441 HvPwrOnCmd_SBMU08_25 "高压控制指令";
CM_ SG_ 2148630441 HvPwrOnCmd_SBMU09_25 "高压控制指令";
CM_ SG_ 2148630441 HvPwrOnCmd_SBMU10_25 "高压控制指令";
CM_ SG_ 2148630441 HvPwrOnCmd_SBMU11_25 "高压控制指令";
CM_ SG_ 2148630441 HvPwrOnCmd_SBMU12_25 "高压控制指令";
CM_ SG_ 2148630441 HvPwrOnCmd_SBMU13_25 "高压控制指令";
CM_ SG_ 2148630441 HvPwrOnCmd_SBMU14_25 "高压控制指令";
CM_ SG_ 2148630441 HvPwrOnCmd_SBMU15_25 "高压控制指令";
CM_ SG_ 2148630441 HvPwrOnCmd_SBMU16_25 "高压控制指令";
CM_ SG_ 2148630441 HvPwrOnCmd_SBMU17_25 "高压控制指令";
CM_ SG_ 2148630441 HvPwrOnCmd_SBMU18_25 "高压控制指令";
CM_ SG_ 2148630441 HvPwrOnCmd_SBMU19_25 "高压控制指令";
CM_ SG_ 2148630441 HvPwrOnCmd_SBMU20_25 "高压控制指令";
CM_ SG_ 2148630441 HvPwrOnCmd_SBMU21_25 "高压控制指令";
CM_ SG_ 2148630441 HvPwrOnCmd_SBMU22_25 "高压控制指令";
CM_ SG_ 2148630441 HvPwrOnCmd_SBMU23_25 "高压控制指令";
CM_ SG_ 2148630441 HvPwrOnCmd_SBMU24_25 "高压控制指令";
CM_ SG_ 2148630441 HvPwrOnCmd_SBMU25_25 "高压控制指令";
CM_ SG_ 2148630441 HvPwrOnCmd_SBMU26_25 "高压控制指令";
CM_ SG_ 2148630441 HvPwrOnCmd_SBMU27_25 "高压控制指令";
CM_ SG_ 2148630441 HvPwrOnCmd_SBMU28_25 "高压控制指令";
CM_ SG_ 2148630441 HvPwrOnCmd_SBMU29_25 "高压控制指令";
CM_ SG_ 2148630441 HvPwrOnCmd_SBMU30_25 "高压控制指令";
CM_ SG_ 2148630441 HvPwrOnCmd_SBMU31_25 "高压控制指令";
CM_ SG_ 2148630441 HvPwrOnCmd_SBMU32_25 "高压控制指令";
CM_ SG_ 2148630442 HvPwrOnCmd_SBMU01_26 "高压控制指令";
CM_ SG_ 2148630442 HvPwrOnCmd_SBMU02_26 "高压控制指令";
CM_ SG_ 2148630442 HvPwrOnCmd_SBMU03_26 "高压控制指令";
CM_ SG_ 2148630442 HvPwrOnCmd_SBMU04_26 "高压控制指令";
CM_ SG_ 2148630442 HvPwrOnCmd_SBMU05_26 "高压控制指令";
CM_ SG_ 2148630442 HvPwrOnCmd_SBMU06_26 "高压控制指令";
CM_ SG_ 2148630442 HvPwrOnCmd_SBMU07_26 "高压控制指令";
CM_ SG_ 2148630442 HvPwrOnCmd_SBMU08_26 "高压控制指令";
CM_ SG_ 2148630442 HvPwrOnCmd_SBMU09_26 "高压控制指令";
CM_ SG_ 2148630442 HvPwrOnCmd_SBMU10_26 "高压控制指令";
CM_ SG_ 2148630442 HvPwrOnCmd_SBMU11_26 "高压控制指令";
CM_ SG_ 2148630442 HvPwrOnCmd_SBMU12_26 "高压控制指令";
CM_ SG_ 2148630442 HvPwrOnCmd_SBMU13_26 "高压控制指令";
CM_ SG_ 2148630442 HvPwrOnCmd_SBMU14_26 "高压控制指令";
CM_ SG_ 2148630442 HvPwrOnCmd_SBMU15_26 "高压控制指令";
CM_ SG_ 2148630442 HvPwrOnCmd_SBMU16_26 "高压控制指令";
CM_ SG_ 2148630442 HvPwrOnCmd_SBMU17_26 "高压控制指令";
CM_ SG_ 2148630442 HvPwrOnCmd_SBMU18_26 "高压控制指令";
CM_ SG_ 2148630442 HvPwrOnCmd_SBMU19_26 "高压控制指令";
CM_ SG_ 2148630442 HvPwrOnCmd_SBMU20_26 "高压控制指令";
CM_ SG_ 2148630442 HvPwrOnCmd_SBMU21_26 "高压控制指令";
CM_ SG_ 2148630442 HvPwrOnCmd_SBMU22_26 "高压控制指令";
CM_ SG_ 2148630442 HvPwrOnCmd_SBMU23_26 "高压控制指令";
CM_ SG_ 2148630442 HvPwrOnCmd_SBMU24_26 "高压控制指令";
CM_ SG_ 2148630442 HvPwrOnCmd_SBMU25_26 "高压控制指令";
CM_ SG_ 2148630442 HvPwrOnCmd_SBMU26_26 "高压控制指令";
CM_ SG_ 2148630442 HvPwrOnCmd_SBMU27_26 "高压控制指令";
CM_ SG_ 2148630442 HvPwrOnCmd_SBMU28_26 "高压控制指令";
CM_ SG_ 2148630442 HvPwrOnCmd_SBMU29_26 "高压控制指令";
CM_ SG_ 2148630442 HvPwrOnCmd_SBMU30_26 "高压控制指令";
CM_ SG_ 2148630442 HvPwrOnCmd_SBMU31_26 "高压控制指令";
CM_ SG_ 2148630442 HvPwrOnCmd_SBMU32_26 "高压控制指令";
CM_ SG_ 2148630443 HvPwrOnCmd_SBMU01_27 "高压控制指令";
CM_ SG_ 2148630443 HvPwrOnCmd_SBMU02_27 "高压控制指令";
CM_ SG_ 2148630443 HvPwrOnCmd_SBMU03_27 "高压控制指令";
CM_ SG_ 2148630443 HvPwrOnCmd_SBMU04_27 "高压控制指令";
CM_ SG_ 2148630443 HvPwrOnCmd_SBMU05_27 "高压控制指令";
CM_ SG_ 2148630443 HvPwrOnCmd_SBMU06_27 "高压控制指令";
CM_ SG_ 2148630443 HvPwrOnCmd_SBMU07_27 "高压控制指令";
CM_ SG_ 2148630443 HvPwrOnCmd_SBMU08_27 "高压控制指令";
CM_ SG_ 2148630443 HvPwrOnCmd_SBMU09_27 "高压控制指令";
CM_ SG_ 2148630443 HvPwrOnCmd_SBMU10_27 "高压控制指令";
CM_ SG_ 2148630443 HvPwrOnCmd_SBMU11_27 "高压控制指令";
CM_ SG_ 2148630443 HvPwrOnCmd_SBMU12_27 "高压控制指令";
CM_ SG_ 2148630443 HvPwrOnCmd_SBMU13_27 "高压控制指令";
CM_ SG_ 2148630443 HvPwrOnCmd_SBMU14_27 "高压控制指令";
CM_ SG_ 2148630443 HvPwrOnCmd_SBMU15_27 "高压控制指令";
CM_ SG_ 2148630443 HvPwrOnCmd_SBMU16_27 "高压控制指令";
CM_ SG_ 2148630443 HvPwrOnCmd_SBMU17_27 "高压控制指令";
CM_ SG_ 2148630443 HvPwrOnCmd_SBMU18_27 "高压控制指令";
CM_ SG_ 2148630443 HvPwrOnCmd_SBMU19_27 "高压控制指令";
CM_ SG_ 2148630443 HvPwrOnCmd_SBMU20_27 "高压控制指令";
CM_ SG_ 2148630443 HvPwrOnCmd_SBMU21_27 "高压控制指令";
CM_ SG_ 2148630443 HvPwrOnCmd_SBMU22_27 "高压控制指令";
CM_ SG_ 2148630443 HvPwrOnCmd_SBMU23_27 "高压控制指令";
CM_ SG_ 2148630443 HvPwrOnCmd_SBMU24_27 "高压控制指令";
CM_ SG_ 2148630443 HvPwrOnCmd_SBMU25_27 "高压控制指令";
CM_ SG_ 2148630443 HvPwrOnCmd_SBMU26_27 "高压控制指令";
CM_ SG_ 2148630443 HvPwrOnCmd_SBMU27_27 "高压控制指令";
CM_ SG_ 2148630443 HvPwrOnCmd_SBMU28_27 "高压控制指令";
CM_ SG_ 2148630443 HvPwrOnCmd_SBMU29_27 "高压控制指令";
CM_ SG_ 2148630443 HvPwrOnCmd_SBMU30_27 "高压控制指令";
CM_ SG_ 2148630443 HvPwrOnCmd_SBMU31_27 "高压控制指令";
CM_ SG_ 2148630443 HvPwrOnCmd_SBMU32_27 "高压控制指令";
CM_ SG_ 2148630444 HvPwrOnCmd_SBMU01_28 "高压控制指令";
CM_ SG_ 2148630444 HvPwrOnCmd_SBMU02_28 "高压控制指令";
CM_ SG_ 2148630444 HvPwrOnCmd_SBMU03_28 "高压控制指令";
CM_ SG_ 2148630444 HvPwrOnCmd_SBMU04_28 "高压控制指令";
CM_ SG_ 2148630444 HvPwrOnCmd_SBMU05_28 "高压控制指令";
CM_ SG_ 2148630444 HvPwrOnCmd_SBMU06_28 "高压控制指令";
CM_ SG_ 2148630444 HvPwrOnCmd_SBMU07_28 "高压控制指令";
CM_ SG_ 2148630444 HvPwrOnCmd_SBMU08_28 "高压控制指令";
CM_ SG_ 2148630444 HvPwrOnCmd_SBMU09_28 "高压控制指令";
CM_ SG_ 2148630444 HvPwrOnCmd_SBMU10_28 "高压控制指令";
CM_ SG_ 2148630444 HvPwrOnCmd_SBMU11_28 "高压控制指令";
CM_ SG_ 2148630444 HvPwrOnCmd_SBMU12_28 "高压控制指令";
CM_ SG_ 2148630444 HvPwrOnCmd_SBMU13_28 "高压控制指令";
CM_ SG_ 2148630444 HvPwrOnCmd_SBMU14_28 "高压控制指令";
CM_ SG_ 2148630444 HvPwrOnCmd_SBMU15_28 "高压控制指令";
CM_ SG_ 2148630444 HvPwrOnCmd_SBMU16_28 "高压控制指令";
CM_ SG_ 2148630444 HvPwrOnCmd_SBMU17_28 "高压控制指令";
CM_ SG_ 2148630444 HvPwrOnCmd_SBMU18_28 "高压控制指令";
CM_ SG_ 2148630444 HvPwrOnCmd_SBMU19_28 "高压控制指令";
CM_ SG_ 2148630444 HvPwrOnCmd_SBMU20_28 "高压控制指令";
CM_ SG_ 2148630444 HvPwrOnCmd_SBMU21_28 "高压控制指令";
CM_ SG_ 2148630444 HvPwrOnCmd_SBMU22_28 "高压控制指令";
CM_ SG_ 2148630444 HvPwrOnCmd_SBMU23_28 "高压控制指令";
CM_ SG_ 2148630444 HvPwrOnCmd_SBMU24_28 "高压控制指令";
CM_ SG_ 2148630444 HvPwrOnCmd_SBMU25_28 "高压控制指令";
CM_ SG_ 2148630444 HvPwrOnCmd_SBMU26_28 "高压控制指令";
CM_ SG_ 2148630444 HvPwrOnCmd_SBMU27_28 "高压控制指令";
CM_ SG_ 2148630444 HvPwrOnCmd_SBMU28_28 "高压控制指令";
CM_ SG_ 2148630444 HvPwrOnCmd_SBMU29_28 "高压控制指令";
CM_ SG_ 2148630444 HvPwrOnCmd_SBMU30_28 "高压控制指令";
CM_ SG_ 2148630444 HvPwrOnCmd_SBMU31_28 "高压控制指令";
CM_ SG_ 2148630444 HvPwrOnCmd_SBMU32_28 "高压控制指令";
CM_ SG_ 2148630445 HvPwrOnCmd_SBMU01_29 "高压控制指令";
CM_ SG_ 2148630445 HvPwrOnCmd_SBMU02_29 "高压控制指令";
CM_ SG_ 2148630445 HvPwrOnCmd_SBMU03_29 "高压控制指令";
CM_ SG_ 2148630445 HvPwrOnCmd_SBMU04_29 "高压控制指令";
CM_ SG_ 2148630445 HvPwrOnCmd_SBMU05_29 "高压控制指令";
CM_ SG_ 2148630445 HvPwrOnCmd_SBMU06_29 "高压控制指令";
CM_ SG_ 2148630445 HvPwrOnCmd_SBMU07_29 "高压控制指令";
CM_ SG_ 2148630445 HvPwrOnCmd_SBMU08_29 "高压控制指令";
CM_ SG_ 2148630445 HvPwrOnCmd_SBMU09_29 "高压控制指令";
CM_ SG_ 2148630445 HvPwrOnCmd_SBMU10_29 "高压控制指令";
CM_ SG_ 2148630445 HvPwrOnCmd_SBMU11_29 "高压控制指令";
CM_ SG_ 2148630445 HvPwrOnCmd_SBMU12_29 "高压控制指令";
CM_ SG_ 2148630445 HvPwrOnCmd_SBMU13_29 "高压控制指令";
CM_ SG_ 2148630445 HvPwrOnCmd_SBMU14_29 "高压控制指令";
CM_ SG_ 2148630445 HvPwrOnCmd_SBMU15_29 "高压控制指令";
CM_ SG_ 2148630445 HvPwrOnCmd_SBMU16_29 "高压控制指令";
CM_ SG_ 2148630445 HvPwrOnCmd_SBMU17_29 "高压控制指令";
CM_ SG_ 2148630445 HvPwrOnCmd_SBMU18_29 "高压控制指令";
CM_ SG_ 2148630445 HvPwrOnCmd_SBMU19_29 "高压控制指令";
CM_ SG_ 2148630445 HvPwrOnCmd_SBMU20_29 "高压控制指令";
CM_ SG_ 2148630445 HvPwrOnCmd_SBMU21_29 "高压控制指令";
CM_ SG_ 2148630445 HvPwrOnCmd_SBMU22_29 "高压控制指令";
CM_ SG_ 2148630445 HvPwrOnCmd_SBMU23_29 "高压控制指令";
CM_ SG_ 2148630445 HvPwrOnCmd_SBMU24_29 "高压控制指令";
CM_ SG_ 2148630445 HvPwrOnCmd_SBMU25_29 "高压控制指令";
CM_ SG_ 2148630445 HvPwrOnCmd_SBMU26_29 "高压控制指令";
CM_ SG_ 2148630445 HvPwrOnCmd_SBMU27_29 "高压控制指令";
CM_ SG_ 2148630445 HvPwrOnCmd_SBMU28_29 "高压控制指令";
CM_ SG_ 2148630445 HvPwrOnCmd_SBMU29_29 "高压控制指令";
CM_ SG_ 2148630445 HvPwrOnCmd_SBMU30_29 "高压控制指令";
CM_ SG_ 2148630445 HvPwrOnCmd_SBMU31_29 "高压控制指令";
CM_ SG_ 2148630445 HvPwrOnCmd_SBMU32_29 "高压控制指令";
CM_ SG_ 2148630446 HvPwrOnCmd_SBMU01_30 "高压控制指令";
CM_ SG_ 2148630446 HvPwrOnCmd_SBMU02_30 "高压控制指令";
CM_ SG_ 2148630446 HvPwrOnCmd_SBMU03_30 "高压控制指令";
CM_ SG_ 2148630446 HvPwrOnCmd_SBMU04_30 "高压控制指令";
CM_ SG_ 2148630446 HvPwrOnCmd_SBMU05_30 "高压控制指令";
CM_ SG_ 2148630446 HvPwrOnCmd_SBMU06_30 "高压控制指令";
CM_ SG_ 2148630446 HvPwrOnCmd_SBMU07_30 "高压控制指令";
CM_ SG_ 2148630446 HvPwrOnCmd_SBMU08_30 "高压控制指令";
CM_ SG_ 2148630446 HvPwrOnCmd_SBMU09_30 "高压控制指令";
CM_ SG_ 2148630446 HvPwrOnCmd_SBMU10_30 "高压控制指令";
CM_ SG_ 2148630446 HvPwrOnCmd_SBMU11_30 "高压控制指令";
CM_ SG_ 2148630446 HvPwrOnCmd_SBMU12_30 "高压控制指令";
CM_ SG_ 2148630446 HvPwrOnCmd_SBMU13_30 "高压控制指令";
CM_ SG_ 2148630446 HvPwrOnCmd_SBMU14_30 "高压控制指令";
CM_ SG_ 2148630446 HvPwrOnCmd_SBMU15_30 "高压控制指令";
CM_ SG_ 2148630446 HvPwrOnCmd_SBMU16_30 "高压控制指令";
CM_ SG_ 2148630446 HvPwrOnCmd_SBMU17_30 "高压控制指令";
CM_ SG_ 2148630446 HvPwrOnCmd_SBMU18_30 "高压控制指令";
CM_ SG_ 2148630446 HvPwrOnCmd_SBMU19_30 "高压控制指令";
CM_ SG_ 2148630446 HvPwrOnCmd_SBMU20_30 "高压控制指令";
CM_ SG_ 2148630446 HvPwrOnCmd_SBMU21_30 "高压控制指令";
CM_ SG_ 2148630446 HvPwrOnCmd_SBMU22_30 "高压控制指令";
CM_ SG_ 2148630446 HvPwrOnCmd_SBMU23_30 "高压控制指令";
CM_ SG_ 2148630446 HvPwrOnCmd_SBMU24_30 "高压控制指令";
CM_ SG_ 2148630446 HvPwrOnCmd_SBMU25_30 "高压控制指令";
CM_ SG_ 2148630446 HvPwrOnCmd_SBMU26_30 "高压控制指令";
CM_ SG_ 2148630446 HvPwrOnCmd_SBMU27_30 "高压控制指令";
CM_ SG_ 2148630446 HvPwrOnCmd_SBMU28_30 "高压控制指令";
CM_ SG_ 2148630446 HvPwrOnCmd_SBMU29_30 "高压控制指令";
CM_ SG_ 2148630446 HvPwrOnCmd_SBMU30_30 "高压控制指令";
CM_ SG_ 2148630446 HvPwrOnCmd_SBMU31_30 "高压控制指令";
CM_ SG_ 2148630446 HvPwrOnCmd_SBMU32_30 "高压控制指令";
CM_ SG_ 2148630447 HvPwrOnCmd_SBMU01_31 "高压控制指令";
CM_ SG_ 2148630447 HvPwrOnCmd_SBMU02_31 "高压控制指令";
CM_ SG_ 2148630447 HvPwrOnCmd_SBMU03_31 "高压控制指令";
CM_ SG_ 2148630447 HvPwrOnCmd_SBMU04_31 "高压控制指令";
CM_ SG_ 2148630447 HvPwrOnCmd_SBMU05_31 "高压控制指令";
CM_ SG_ 2148630447 HvPwrOnCmd_SBMU06_31 "高压控制指令";
CM_ SG_ 2148630447 HvPwrOnCmd_SBMU07_31 "高压控制指令";
CM_ SG_ 2148630447 HvPwrOnCmd_SBMU08_31 "高压控制指令";
CM_ SG_ 2148630447 HvPwrOnCmd_SBMU09_31 "高压控制指令";
CM_ SG_ 2148630447 HvPwrOnCmd_SBMU10_31 "高压控制指令";
CM_ SG_ 2148630447 HvPwrOnCmd_SBMU11_31 "高压控制指令";
CM_ SG_ 2148630447 HvPwrOnCmd_SBMU12_31 "高压控制指令";
CM_ SG_ 2148630447 HvPwrOnCmd_SBMU13_31 "高压控制指令";
CM_ SG_ 2148630447 HvPwrOnCmd_SBMU14_31 "高压控制指令";
CM_ SG_ 2148630447 HvPwrOnCmd_SBMU15_31 "高压控制指令";
CM_ SG_ 2148630447 HvPwrOnCmd_SBMU16_31 "高压控制指令";
CM_ SG_ 2148630447 HvPwrOnCmd_SBMU17_31 "高压控制指令";
CM_ SG_ 2148630447 HvPwrOnCmd_SBMU18_31 "高压控制指令";
CM_ SG_ 2148630447 HvPwrOnCmd_SBMU19_31 "高压控制指令";
CM_ SG_ 2148630447 HvPwrOnCmd_SBMU20_31 "高压控制指令";
CM_ SG_ 2148630447 HvPwrOnCmd_SBMU21_31 "高压控制指令";
CM_ SG_ 2148630447 HvPwrOnCmd_SBMU22_31 "高压控制指令";
CM_ SG_ 2148630447 HvPwrOnCmd_SBMU23_31 "高压控制指令";
CM_ SG_ 2148630447 HvPwrOnCmd_SBMU24_31 "高压控制指令";
CM_ SG_ 2148630447 HvPwrOnCmd_SBMU25_31 "高压控制指令";
CM_ SG_ 2148630447 HvPwrOnCmd_SBMU26_31 "高压控制指令";
CM_ SG_ 2148630447 HvPwrOnCmd_SBMU27_31 "高压控制指令";
CM_ SG_ 2148630447 HvPwrOnCmd_SBMU28_31 "高压控制指令";
CM_ SG_ 2148630447 HvPwrOnCmd_SBMU29_31 "高压控制指令";
CM_ SG_ 2148630447 HvPwrOnCmd_SBMU30_31 "高压控制指令";
CM_ SG_ 2148630447 HvPwrOnCmd_SBMU31_31 "高压控制指令";
CM_ SG_ 2148630447 HvPwrOnCmd_SBMU32_31 "高压控制指令";
CM_ SG_ 2148695953 M2S_CMD2_CRC_01 "MBMU发送给SBMU命令帧2的CRC";
CM_ SG_ 2148695953 M2S_CMD2_ALIV_01 "MBMU发送给SBMU命令帧2的生命信号，0~15循环";
CM_ SG_ 2148695953 M2S_CMD2_PowerDown_01 "MBMU发送给所有SMBU的低压下电命令";
CM_ SG_ 2148695953 M2S_CMD2_FanCtrl_01 "MBMU发送给所有SMBU的风扇控制状态";
CM_ SG_ 2148695953 M2S_CMD2_SleepCsc_01 "SBMU收到外部休眠CSC指令";
CM_ SG_ 2148695953 M2S_CMD2_Data3_01 "故障清除指令类型";
CM_ SG_ 2148695953 M2S_CMD2_FullChgFlgFromMBMU_01 "SOC修正指令";
CM_ SG_ 2148695953 M2S_CMD2_Data4_01 "预留";
CM_ SG_ 2148695953 M2S_MinSBMUAveTmpValue_01 "
系统温差调节参考温度";
CM_ SG_ 2148695953 M2S_CMD2_Data6_01 "预留";
CM_ SG_ 2148695953 M2S_CMD2_Data7_01 "预留";
CM_ SG_ 2148695953 M2S_CMD2_Data8_01 "预留";
CM_ SG_ 2148695954 M2S_CMD2_CRC_02 "MBMU发送给SBMU命令帧2的CRC";
CM_ SG_ 2148695954 M2S_CMD2_ALIV_02 "MBMU发送给SBMU命令帧2的生命信号，0~15循环";
CM_ SG_ 2148695954 M2S_CMD2_PowerDown_02 "MBMU发送给所有SMBU的低压下电命令";
CM_ SG_ 2148695954 M2S_CMD2_FanCtrl_02 "MBMU发送给所有SMBU的风扇控制状态";
CM_ SG_ 2148695954 M2S_CMD2_SleepCsc_02 "SBMU收到外部休眠CSC指令";
CM_ SG_ 2148695954 M2S_CMD2_Data3_02 "故障清除指令类型";
CM_ SG_ 2148695954 M2S_CMD2_FullChgFlgFromMBMU_02 "SOC修正指令";
CM_ SG_ 2148695954 M2S_CMD2_Data4_02 "预留";
CM_ SG_ 2148695954 M2S_MinSBMUAveTmpValue_02 "
系统温差调节参考温度";
CM_ SG_ 2148695954 M2S_CMD2_Data6_02 "预留";
CM_ SG_ 2148695954 M2S_CMD2_Data7_02 "预留";
CM_ SG_ 2148695954 M2S_CMD2_Data8_02 "预留";
CM_ SG_ 2148695955 M2S_CMD2_CRC_03 "MBMU发送给SBMU命令帧2的CRC";
CM_ SG_ 2148695955 M2S_CMD2_ALIV_03 "MBMU发送给SBMU命令帧2的生命信号，0~15循环";
CM_ SG_ 2148695955 M2S_CMD2_PowerDown_03 "MBMU发送给所有SMBU的低压下电命令";
CM_ SG_ 2148695955 M2S_CMD2_FanCtrl_03 "MBMU发送给所有SMBU的风扇控制状态";
CM_ SG_ 2148695955 M2S_CMD2_SleepCsc_03 "SBMU收到外部休眠CSC指令";
CM_ SG_ 2148695955 M2S_CMD2_Data3_03 "故障清除指令类型";
CM_ SG_ 2148695955 M2S_CMD2_FullChgFlgFromMBMU_03 "SOC修正指令";
CM_ SG_ 2148695955 M2S_CMD2_Data4_03 "预留";
CM_ SG_ 2148695955 M2S_MinSBMUAveTmpValue_03 "
系统温差调节参考温度";
CM_ SG_ 2148695955 M2S_CMD2_Data6_03 "预留";
CM_ SG_ 2148695955 M2S_CMD2_Data7_03 "预留";
CM_ SG_ 2148695955 M2S_CMD2_Data8_03 "预留";
CM_ SG_ 2148695956 M2S_CMD2_CRC_04 "MBMU发送给SBMU命令帧2的CRC";
CM_ SG_ 2148695956 M2S_CMD2_ALIV_04 "MBMU发送给SBMU命令帧2的生命信号，0~15循环";
CM_ SG_ 2148695956 M2S_CMD2_PowerDown_04 "MBMU发送给所有SMBU的低压下电命令";
CM_ SG_ 2148695956 M2S_CMD2_FanCtrl_04 "MBMU发送给所有SMBU的风扇控制状态";
CM_ SG_ 2148695956 M2S_CMD2_SleepCsc_04 "SBMU收到外部休眠CSC指令";
CM_ SG_ 2148695956 M2S_CMD2_Data3_04 "故障清除指令类型";
CM_ SG_ 2148695956 M2S_CMD2_FullChgFlgFromMBMU_04 "SOC修正指令";
CM_ SG_ 2148695956 M2S_CMD2_Data4_04 "预留";
CM_ SG_ 2148695956 M2S_MinSBMUAveTmpValue_04 "
系统温差调节参考温度";
CM_ SG_ 2148695956 M2S_CMD2_Data6_04 "预留";
CM_ SG_ 2148695956 M2S_CMD2_Data7_04 "预留";
CM_ SG_ 2148695956 M2S_CMD2_Data8_04 "预留";
CM_ SG_ 2148695957 M2S_CMD2_CRC_05 "MBMU发送给SBMU命令帧2的CRC";
CM_ SG_ 2148695957 M2S_CMD2_ALIV_05 "MBMU发送给SBMU命令帧2的生命信号，0~15循环";
CM_ SG_ 2148695957 M2S_CMD2_PowerDown_05 "MBMU发送给所有SMBU的低压下电命令";
CM_ SG_ 2148695957 M2S_CMD2_FanCtrl_05 "MBMU发送给所有SMBU的风扇控制状态";
CM_ SG_ 2148695957 M2S_CMD2_SleepCsc_05 "SBMU收到外部休眠CSC指令";
CM_ SG_ 2148695957 M2S_CMD2_Data3_05 "故障清除指令类型";
CM_ SG_ 2148695957 M2S_CMD2_FullChgFlgFromMBMU_05 "SOC修正指令";
CM_ SG_ 2148695957 M2S_CMD2_Data4_05 "预留";
CM_ SG_ 2148695957 M2S_MinSBMUAveTmpValue_05 "
系统温差调节参考温度";
CM_ SG_ 2148695957 M2S_CMD2_Data6_05 "预留";
CM_ SG_ 2148695957 M2S_CMD2_Data7_05 "预留";
CM_ SG_ 2148695957 M2S_CMD2_Data8_05 "预留";
CM_ SG_ 2148695958 M2S_CMD2_CRC_06 "MBMU发送给SBMU命令帧2的CRC";
CM_ SG_ 2148695958 M2S_CMD2_ALIV_06 "MBMU发送给SBMU命令帧2的生命信号，0~15循环";
CM_ SG_ 2148695958 M2S_CMD2_PowerDown_06 "MBMU发送给所有SMBU的低压下电命令";
CM_ SG_ 2148695958 M2S_CMD2_FanCtrl_06 "MBMU发送给所有SMBU的风扇控制状态";
CM_ SG_ 2148695958 M2S_CMD2_SleepCsc_06 "SBMU收到外部休眠CSC指令";
CM_ SG_ 2148695958 M2S_CMD2_Data3_06 "故障清除指令类型";
CM_ SG_ 2148695958 M2S_CMD2_FullChgFlgFromMBMU_06 "SOC修正指令";
CM_ SG_ 2148695958 M2S_CMD2_Data4_06 "预留";
CM_ SG_ 2148695958 M2S_MinSBMUAveTmpValue_06 "
系统温差调节参考温度";
CM_ SG_ 2148695958 M2S_CMD2_Data6_06 "预留";
CM_ SG_ 2148695958 M2S_CMD2_Data7_06 "预留";
CM_ SG_ 2148695958 M2S_CMD2_Data8_06 "预留";
CM_ SG_ 2148695959 M2S_CMD2_CRC_07 "MBMU发送给SBMU命令帧2的CRC";
CM_ SG_ 2148695959 M2S_CMD2_ALIV_07 "MBMU发送给SBMU命令帧2的生命信号，0~15循环";
CM_ SG_ 2148695959 M2S_CMD2_PowerDown_07 "MBMU发送给所有SMBU的低压下电命令";
CM_ SG_ 2148695959 M2S_CMD2_FanCtrl_07 "MBMU发送给所有SMBU的风扇控制状态";
CM_ SG_ 2148695959 M2S_CMD2_SleepCsc_07 "SBMU收到外部休眠CSC指令";
CM_ SG_ 2148695959 M2S_CMD2_Data3_07 "故障清除指令类型";
CM_ SG_ 2148695959 M2S_CMD2_FullChgFlgFromMBMU_07 "SOC修正指令";
CM_ SG_ 2148695959 M2S_CMD2_Data4_07 "预留";
CM_ SG_ 2148695959 M2S_MinSBMUAveTmpValue_07 "
系统温差调节参考温度";
CM_ SG_ 2148695959 M2S_CMD2_Data6_07 "预留";
CM_ SG_ 2148695959 M2S_CMD2_Data7_07 "预留";
CM_ SG_ 2148695959 M2S_CMD2_Data8_07 "预留";
CM_ SG_ 2148695960 M2S_CMD2_CRC_08 "MBMU发送给SBMU命令帧2的CRC";
CM_ SG_ 2148695960 M2S_CMD2_ALIV_08 "MBMU发送给SBMU命令帧2的生命信号，0~15循环";
CM_ SG_ 2148695960 M2S_CMD2_PowerDown_08 "MBMU发送给所有SMBU的低压下电命令";
CM_ SG_ 2148695960 M2S_CMD2_FanCtrl_08 "MBMU发送给所有SMBU的风扇控制状态";
CM_ SG_ 2148695960 M2S_CMD2_SleepCsc_08 "SBMU收到外部休眠CSC指令";
CM_ SG_ 2148695960 M2S_CMD2_Data3_08 "故障清除指令类型";
CM_ SG_ 2148695960 M2S_CMD2_FullChgFlgFromMBMU_08 "SOC修正指令";
CM_ SG_ 2148695960 M2S_CMD2_Data4_08 "预留";
CM_ SG_ 2148695960 M2S_MinSBMUAveTmpValue_08 "
系统温差调节参考温度";
CM_ SG_ 2148695960 M2S_CMD2_Data6_08 "预留";
CM_ SG_ 2148695960 M2S_CMD2_Data7_08 "预留";
CM_ SG_ 2148695960 M2S_CMD2_Data8_08 "预留";
CM_ SG_ 2148695961 M2S_CMD2_CRC_09 "MBMU发送给SBMU命令帧2的CRC";
CM_ SG_ 2148695961 M2S_CMD2_ALIV_09 "MBMU发送给SBMU命令帧2的生命信号，0~15循环";
CM_ SG_ 2148695961 M2S_CMD2_PowerDown_09 "MBMU发送给所有SMBU的低压下电命令";
CM_ SG_ 2148695961 M2S_CMD2_FanCtrl_09 "MBMU发送给所有SMBU的风扇控制状态";
CM_ SG_ 2148695961 M2S_CMD2_SleepCsc_09 "SBMU收到外部休眠CSC指令";
CM_ SG_ 2148695961 M2S_CMD2_Data3_09 "故障清除指令类型";
CM_ SG_ 2148695961 M2S_CMD2_FullChgFlgFromMBMU_09 "SOC修正指令";
CM_ SG_ 2148695961 M2S_CMD2_Data4_09 "预留";
CM_ SG_ 2148695961 M2S_MinSBMUAveTmpValue_09 "
系统温差调节参考温度";
CM_ SG_ 2148695961 M2S_CMD2_Data6_09 "预留";
CM_ SG_ 2148695961 M2S_CMD2_Data7_09 "预留";
CM_ SG_ 2148695961 M2S_CMD2_Data8_09 "预留";
CM_ SG_ 2148695962 M2S_CMD2_CRC_10 "MBMU发送给SBMU命令帧2的CRC";
CM_ SG_ 2148695962 M2S_CMD2_ALIV_10 "MBMU发送给SBMU命令帧2的生命信号，0~15循环";
CM_ SG_ 2148695962 M2S_CMD2_PowerDown_10 "MBMU发送给所有SMBU的低压下电命令";
CM_ SG_ 2148695962 M2S_CMD2_FanCtrl_10 "MBMU发送给所有SMBU的风扇控制状态";
CM_ SG_ 2148695962 M2S_CMD2_SleepCsc_10 "SBMU收到外部休眠CSC指令";
CM_ SG_ 2148695962 M2S_CMD2_Data3_10 "故障清除指令类型";
CM_ SG_ 2148695962 M2S_CMD2_FullChgFlgFromMBMU_10 "SOC修正指令";
CM_ SG_ 2148695962 M2S_CMD2_Data4_10 "预留";
CM_ SG_ 2148695962 M2S_MinSBMUAveTmpValue_10 "
系统温差调节参考温度";
CM_ SG_ 2148695962 M2S_CMD2_Data6_10 "预留";
CM_ SG_ 2148695962 M2S_CMD2_Data7_10 "预留";
CM_ SG_ 2148695962 M2S_CMD2_Data8_10 "预留";
CM_ SG_ 2148695963 M2S_CMD2_CRC_11 "MBMU发送给SBMU命令帧2的CRC";
CM_ SG_ 2148695963 M2S_CMD2_ALIV_11 "MBMU发送给SBMU命令帧2的生命信号，0~15循环";
CM_ SG_ 2148695963 M2S_CMD2_PowerDown_11 "MBMU发送给所有SMBU的低压下电命令";
CM_ SG_ 2148695963 M2S_CMD2_FanCtrl_11 "MBMU发送给所有SMBU的风扇控制状态";
CM_ SG_ 2148695963 M2S_CMD2_SleepCsc_11 "SBMU收到外部休眠CSC指令";
CM_ SG_ 2148695963 M2S_CMD2_Data3_11 "故障清除指令类型";
CM_ SG_ 2148695963 M2S_CMD2_FullChgFlgFromMBMU_11 "SOC修正指令";
CM_ SG_ 2148695963 M2S_CMD2_Data4_11 "预留";
CM_ SG_ 2148695963 M2S_MinSBMUAveTmpValue_11 "
系统温差调节参考温度";
CM_ SG_ 2148695963 M2S_CMD2_Data6_11 "预留";
CM_ SG_ 2148695963 M2S_CMD2_Data7_11 "预留";
CM_ SG_ 2148695963 M2S_CMD2_Data8_11 "预留";
CM_ SG_ 2148695964 M2S_CMD2_CRC_12 "MBMU发送给SBMU命令帧2的CRC";
CM_ SG_ 2148695964 M2S_CMD2_ALIV_12 "MBMU发送给SBMU命令帧2的生命信号，0~15循环";
CM_ SG_ 2148695964 M2S_CMD2_PowerDown_12 "MBMU发送给所有SMBU的低压下电命令";
CM_ SG_ 2148695964 M2S_CMD2_FanCtrl_12 "MBMU发送给所有SMBU的风扇控制状态";
CM_ SG_ 2148695964 M2S_CMD2_SleepCsc_12 "SBMU收到外部休眠CSC指令";
CM_ SG_ 2148695964 M2S_CMD2_Data3_12 "故障清除指令类型";
CM_ SG_ 2148695964 M2S_CMD2_FullChgFlgFromMBMU_12 "SOC修正指令";
CM_ SG_ 2148695964 M2S_CMD2_Data4_12 "预留";
CM_ SG_ 2148695964 M2S_MinSBMUAveTmpValue_12 "
系统温差调节参考温度";
CM_ SG_ 2148695964 M2S_CMD2_Data6_12 "预留";
CM_ SG_ 2148695964 M2S_CMD2_Data7_12 "预留";
CM_ SG_ 2148695964 M2S_CMD2_Data8_12 "预留";
CM_ SG_ 2148695965 M2S_CMD2_CRC_13 "MBMU发送给SBMU命令帧2的CRC";
CM_ SG_ 2148695965 M2S_CMD2_ALIV_13 "MBMU发送给SBMU命令帧2的生命信号，0~15循环";
CM_ SG_ 2148695965 M2S_CMD2_PowerDown_13 "MBMU发送给所有SMBU的低压下电命令";
CM_ SG_ 2148695965 M2S_CMD2_FanCtrl_13 "MBMU发送给所有SMBU的风扇控制状态";
CM_ SG_ 2148695965 M2S_CMD2_SleepCsc_13 "SBMU收到外部休眠CSC指令";
CM_ SG_ 2148695965 M2S_CMD2_Data3_13 "故障清除指令类型";
CM_ SG_ 2148695965 M2S_CMD2_FullChgFlgFromMBMU_13 "SOC修正指令";
CM_ SG_ 2148695965 M2S_CMD2_Data4_13 "预留";
CM_ SG_ 2148695965 M2S_MinSBMUAveTmpValue_13 "
系统温差调节参考温度";
CM_ SG_ 2148695965 M2S_CMD2_Data6_13 "预留";
CM_ SG_ 2148695965 M2S_CMD2_Data7_13 "预留";
CM_ SG_ 2148695965 M2S_CMD2_Data8_13 "预留";
CM_ SG_ 2148695966 M2S_CMD2_CRC_14 "MBMU发送给SBMU命令帧2的CRC";
CM_ SG_ 2148695966 M2S_CMD2_ALIV_14 "MBMU发送给SBMU命令帧2的生命信号，0~15循环";
CM_ SG_ 2148695966 M2S_CMD2_PowerDown_14 "MBMU发送给所有SMBU的低压下电命令";
CM_ SG_ 2148695966 M2S_CMD2_FanCtrl_14 "MBMU发送给所有SMBU的风扇控制状态";
CM_ SG_ 2148695966 M2S_CMD2_SleepCsc_14 "SBMU收到外部休眠CSC指令";
CM_ SG_ 2148695966 M2S_CMD2_Data3_14 "故障清除指令类型";
CM_ SG_ 2148695966 M2S_CMD2_FullChgFlgFromMBMU_14 "SOC修正指令";
CM_ SG_ 2148695966 M2S_CMD2_Data4_14 "预留";
CM_ SG_ 2148695966 M2S_MinSBMUAveTmpValue_14 "
系统温差调节参考温度";
CM_ SG_ 2148695966 M2S_CMD2_Data6_14 "预留";
CM_ SG_ 2148695966 M2S_CMD2_Data7_14 "预留";
CM_ SG_ 2148695966 M2S_CMD2_Data8_14 "预留";
CM_ SG_ 2148695967 M2S_CMD2_CRC_15 "MBMU发送给SBMU命令帧2的CRC";
CM_ SG_ 2148695967 M2S_CMD2_ALIV_15 "MBMU发送给SBMU命令帧2的生命信号，0~15循环";
CM_ SG_ 2148695967 M2S_CMD2_PowerDown_15 "MBMU发送给所有SMBU的低压下电命令";
CM_ SG_ 2148695967 M2S_CMD2_FanCtrl_15 "MBMU发送给所有SMBU的风扇控制状态";
CM_ SG_ 2148695967 M2S_CMD2_SleepCsc_15 "SBMU收到外部休眠CSC指令";
CM_ SG_ 2148695967 M2S_CMD2_Data3_15 "故障清除指令类型";
CM_ SG_ 2148695967 M2S_CMD2_FullChgFlgFromMBMU_15 "SOC修正指令";
CM_ SG_ 2148695967 M2S_CMD2_Data4_15 "预留";
CM_ SG_ 2148695967 M2S_MinSBMUAveTmpValue_15 "
系统温差调节参考温度";
CM_ SG_ 2148695967 M2S_CMD2_Data6_15 "预留";
CM_ SG_ 2148695967 M2S_CMD2_Data7_15 "预留";
CM_ SG_ 2148695967 M2S_CMD2_Data8_15 "预留";
CM_ SG_ 2148695968 M2S_CMD2_CRC_16 "MBMU发送给SBMU命令帧2的CRC";
CM_ SG_ 2148695968 M2S_CMD2_ALIV_16 "MBMU发送给SBMU命令帧2的生命信号，0~15循环";
CM_ SG_ 2148695968 M2S_CMD2_PowerDown_16 "MBMU发送给所有SMBU的低压下电命令";
CM_ SG_ 2148695968 M2S_CMD2_FanCtrl_16 "MBMU发送给所有SMBU的风扇控制状态";
CM_ SG_ 2148695968 M2S_CMD2_SleepCsc_16 "SBMU收到外部休眠CSC指令";
CM_ SG_ 2148695968 M2S_CMD2_Data3_16 "故障清除指令类型";
CM_ SG_ 2148695968 M2S_CMD2_FullChgFlgFromMBMU_16 "SOC修正指令";
CM_ SG_ 2148695968 M2S_CMD2_Data4_16 "预留";
CM_ SG_ 2148695968 M2S_MinSBMUAveTmpValue_16 "
系统温差调节参考温度";
CM_ SG_ 2148695968 M2S_CMD2_Data6_16 "预留";
CM_ SG_ 2148695968 M2S_CMD2_Data7_16 "预留";
CM_ SG_ 2148695968 M2S_CMD2_Data8_16 "预留";
CM_ SG_ 2148695969 M2S_CMD2_CRC_17 "MBMU发送给SBMU命令帧2的CRC";
CM_ SG_ 2148695969 M2S_CMD2_ALIV_17 "MBMU发送给SBMU命令帧2的生命信号，0~15循环";
CM_ SG_ 2148695969 M2S_CMD2_PowerDown_17 "MBMU发送给所有SMBU的低压下电命令";
CM_ SG_ 2148695969 M2S_CMD2_FanCtrl_17 "MBMU发送给所有SMBU的风扇控制状态";
CM_ SG_ 2148695969 M2S_CMD2_SleepCsc_17 "SBMU收到外部休眠CSC指令";
CM_ SG_ 2148695969 M2S_CMD2_Data3_17 "故障清除指令类型";
CM_ SG_ 2148695969 M2S_CMD2_FullChgFlgFromMBMU_17 "SOC修正指令";
CM_ SG_ 2148695969 M2S_CMD2_Data4_17 "预留";
CM_ SG_ 2148695969 M2S_MinSBMUAveTmpValue_17 "
系统温差调节参考温度";
CM_ SG_ 2148695969 M2S_CMD2_Data6_17 "预留";
CM_ SG_ 2148695969 M2S_CMD2_Data7_17 "预留";
CM_ SG_ 2148695969 M2S_CMD2_Data8_17 "预留";
CM_ SG_ 2148695970 M2S_CMD2_CRC_18 "MBMU发送给SBMU命令帧2的CRC";
CM_ SG_ 2148695970 M2S_CMD2_ALIV_18 "MBMU发送给SBMU命令帧2的生命信号，0~15循环";
CM_ SG_ 2148695970 M2S_CMD2_PowerDown_18 "MBMU发送给所有SMBU的低压下电命令";
CM_ SG_ 2148695970 M2S_CMD2_FanCtrl_18 "MBMU发送给所有SMBU的风扇控制状态";
CM_ SG_ 2148695970 M2S_CMD2_SleepCsc_18 "SBMU收到外部休眠CSC指令";
CM_ SG_ 2148695970 M2S_CMD2_Data3_18 "故障清除指令类型";
CM_ SG_ 2148695970 M2S_CMD2_FullChgFlgFromMBMU_18 "SOC修正指令";
CM_ SG_ 2148695970 M2S_CMD2_Data4_18 "预留";
CM_ SG_ 2148695970 M2S_MinSBMUAveTmpValue_18 "
系统温差调节参考温度";
CM_ SG_ 2148695970 M2S_CMD2_Data6_18 "预留";
CM_ SG_ 2148695970 M2S_CMD2_Data7_18 "预留";
CM_ SG_ 2148695970 M2S_CMD2_Data8_18 "预留";
CM_ SG_ 2148695971 M2S_CMD2_CRC_19 "MBMU发送给SBMU命令帧2的CRC";
CM_ SG_ 2148695971 M2S_CMD2_ALIV_19 "MBMU发送给SBMU命令帧2的生命信号，0~15循环";
CM_ SG_ 2148695971 M2S_CMD2_PowerDown_19 "MBMU发送给所有SMBU的低压下电命令";
CM_ SG_ 2148695971 M2S_CMD2_FanCtrl_19 "MBMU发送给所有SMBU的风扇控制状态";
CM_ SG_ 2148695971 M2S_CMD2_SleepCsc_19 "SBMU收到外部休眠CSC指令";
CM_ SG_ 2148695971 M2S_CMD2_Data3_19 "故障清除指令类型";
CM_ SG_ 2148695971 M2S_CMD2_FullChgFlgFromMBMU_19 "SOC修正指令";
CM_ SG_ 2148695971 M2S_CMD2_Data4_19 "预留";
CM_ SG_ 2148695971 M2S_MinSBMUAveTmpValue_19 "
系统温差调节参考温度";
CM_ SG_ 2148695971 M2S_CMD2_Data6_19 "预留";
CM_ SG_ 2148695971 M2S_CMD2_Data7_19 "预留";
CM_ SG_ 2148695971 M2S_CMD2_Data8_19 "预留";
CM_ SG_ 2148695972 M2S_CMD2_CRC_20 "MBMU发送给SBMU命令帧2的CRC";
CM_ SG_ 2148695972 M2S_CMD2_ALIV_20 "MBMU发送给SBMU命令帧2的生命信号，0~15循环";
CM_ SG_ 2148695972 M2S_CMD2_PowerDown_20 "MBMU发送给所有SMBU的低压下电命令";
CM_ SG_ 2148695972 M2S_CMD2_FanCtrl_20 "MBMU发送给所有SMBU的风扇控制状态";
CM_ SG_ 2148695972 M2S_CMD2_SleepCsc_20 "SBMU收到外部休眠CSC指令";
CM_ SG_ 2148695972 M2S_CMD2_Data3_20 "故障清除指令类型";
CM_ SG_ 2148695972 M2S_CMD2_FullChgFlgFromMBMU_20 "SOC修正指令";
CM_ SG_ 2148695972 M2S_CMD2_Data4_20 "预留";
CM_ SG_ 2148695972 M2S_MinSBMUAveTmpValue_20 "
系统温差调节参考温度";
CM_ SG_ 2148695972 M2S_CMD2_Data6_20 "预留";
CM_ SG_ 2148695972 M2S_CMD2_Data7_20 "预留";
CM_ SG_ 2148695972 M2S_CMD2_Data8_20 "预留";
CM_ SG_ 2148695973 M2S_CMD2_CRC_21 "MBMU发送给SBMU命令帧2的CRC";
CM_ SG_ 2148695973 M2S_CMD2_ALIV_21 "MBMU发送给SBMU命令帧2的生命信号，0~15循环";
CM_ SG_ 2148695973 M2S_CMD2_PowerDown_21 "MBMU发送给所有SMBU的低压下电命令";
CM_ SG_ 2148695973 M2S_CMD2_FanCtrl_21 "MBMU发送给所有SMBU的风扇控制状态";
CM_ SG_ 2148695973 M2S_CMD2_SleepCsc_21 "SBMU收到外部休眠CSC指令";
CM_ SG_ 2148695973 M2S_CMD2_Data3_21 "故障清除指令类型";
CM_ SG_ 2148695973 M2S_CMD2_FullChgFlgFromMBMU_21 "SOC修正指令";
CM_ SG_ 2148695973 M2S_CMD2_Data4_21 "预留";
CM_ SG_ 2148695973 M2S_MinSBMUAveTmpValue_21 "
系统温差调节参考温度";
CM_ SG_ 2148695973 M2S_CMD2_Data6_21 "预留";
CM_ SG_ 2148695973 M2S_CMD2_Data7_21 "预留";
CM_ SG_ 2148695973 M2S_CMD2_Data8_21 "预留";
CM_ SG_ 2148695974 M2S_CMD2_CRC_22 "MBMU发送给SBMU命令帧2的CRC";
CM_ SG_ 2148695974 M2S_CMD2_ALIV_22 "MBMU发送给SBMU命令帧2的生命信号，0~15循环";
CM_ SG_ 2148695974 M2S_CMD2_PowerDown_22 "MBMU发送给所有SMBU的低压下电命令";
CM_ SG_ 2148695974 M2S_CMD2_FanCtrl_22 "MBMU发送给所有SMBU的风扇控制状态";
CM_ SG_ 2148695974 M2S_CMD2_SleepCsc_22 "SBMU收到外部休眠CSC指令";
CM_ SG_ 2148695974 M2S_CMD2_Data3_22 "故障清除指令类型";
CM_ SG_ 2148695974 M2S_CMD2_FullChgFlgFromMBMU_22 "SOC修正指令";
CM_ SG_ 2148695974 M2S_CMD2_Data4_22 "预留";
CM_ SG_ 2148695974 M2S_MinSBMUAveTmpValue_22 "
系统温差调节参考温度";
CM_ SG_ 2148695974 M2S_CMD2_Data6_22 "预留";
CM_ SG_ 2148695974 M2S_CMD2_Data7_22 "预留";
CM_ SG_ 2148695974 M2S_CMD2_Data8_22 "预留";
CM_ SG_ 2148695975 M2S_CMD2_CRC_23 "MBMU发送给SBMU命令帧2的CRC";
CM_ SG_ 2148695975 M2S_CMD2_ALIV_23 "MBMU发送给SBMU命令帧2的生命信号，0~15循环";
CM_ SG_ 2148695975 M2S_CMD2_PowerDown_23 "MBMU发送给所有SMBU的低压下电命令";
CM_ SG_ 2148695975 M2S_CMD2_FanCtrl_23 "MBMU发送给所有SMBU的风扇控制状态";
CM_ SG_ 2148695975 M2S_CMD2_SleepCsc_23 "SBMU收到外部休眠CSC指令";
CM_ SG_ 2148695975 M2S_CMD2_Data3_23 "故障清除指令类型";
CM_ SG_ 2148695975 M2S_CMD2_FullChgFlgFromMBMU_23 "SOC修正指令";
CM_ SG_ 2148695975 M2S_CMD2_Data4_23 "预留";
CM_ SG_ 2148695975 M2S_MinSBMUAveTmpValue_23 "
系统温差调节参考温度";
CM_ SG_ 2148695975 M2S_CMD2_Data6_23 "预留";
CM_ SG_ 2148695975 M2S_CMD2_Data7_23 "预留";
CM_ SG_ 2148695975 M2S_CMD2_Data8_23 "预留";
CM_ SG_ 2148695976 M2S_CMD2_CRC_24 "MBMU发送给SBMU命令帧2的CRC";
CM_ SG_ 2148695976 M2S_CMD2_ALIV_24 "MBMU发送给SBMU命令帧2的生命信号，0~15循环";
CM_ SG_ 2148695976 M2S_CMD2_PowerDown_24 "MBMU发送给所有SMBU的低压下电命令";
CM_ SG_ 2148695976 M2S_CMD2_FanCtrl_24 "MBMU发送给所有SMBU的风扇控制状态";
CM_ SG_ 2148695976 M2S_CMD2_SleepCsc_24 "SBMU收到外部休眠CSC指令";
CM_ SG_ 2148695976 M2S_CMD2_Data3_24 "故障清除指令类型";
CM_ SG_ 2148695976 M2S_CMD2_FullChgFlgFromMBMU_24 "SOC修正指令";
CM_ SG_ 2148695976 M2S_CMD2_Data4_24 "预留";
CM_ SG_ 2148695976 M2S_MinSBMUAveTmpValue_24 "
系统温差调节参考温度";
CM_ SG_ 2148695976 M2S_CMD2_Data6_24 "预留";
CM_ SG_ 2148695976 M2S_CMD2_Data7_24 "预留";
CM_ SG_ 2148695976 M2S_CMD2_Data8_24 "预留";
CM_ SG_ 2148695977 M2S_CMD2_CRC_25 "MBMU发送给SBMU命令帧2的CRC";
CM_ SG_ 2148695977 M2S_CMD2_ALIV_25 "MBMU发送给SBMU命令帧2的生命信号，0~15循环";
CM_ SG_ 2148695977 M2S_CMD2_PowerDown_25 "MBMU发送给所有SMBU的低压下电命令";
CM_ SG_ 2148695977 M2S_CMD2_FanCtrl_25 "MBMU发送给所有SMBU的风扇控制状态";
CM_ SG_ 2148695977 M2S_CMD2_SleepCsc_25 "SBMU收到外部休眠CSC指令";
CM_ SG_ 2148695977 M2S_CMD2_Data3_25 "故障清除指令类型";
CM_ SG_ 2148695977 M2S_CMD2_FullChgFlgFromMBMU_25 "SOC修正指令";
CM_ SG_ 2148695977 M2S_CMD2_Data4_25 "预留";
CM_ SG_ 2148695977 M2S_MinSBMUAveTmpValue_25 "
系统温差调节参考温度";
CM_ SG_ 2148695977 M2S_CMD2_Data6_25 "预留";
CM_ SG_ 2148695977 M2S_CMD2_Data7_25 "预留";
CM_ SG_ 2148695977 M2S_CMD2_Data8_25 "预留";
CM_ SG_ 2148695978 M2S_CMD2_CRC_26 "MBMU发送给SBMU命令帧2的CRC";
CM_ SG_ 2148695978 M2S_CMD2_ALIV_26 "MBMU发送给SBMU命令帧2的生命信号，0~15循环";
CM_ SG_ 2148695978 M2S_CMD2_PowerDown_26 "MBMU发送给所有SMBU的低压下电命令";
CM_ SG_ 2148695978 M2S_CMD2_FanCtrl_26 "MBMU发送给所有SMBU的风扇控制状态";
CM_ SG_ 2148695978 M2S_CMD2_SleepCsc_26 "SBMU收到外部休眠CSC指令";
CM_ SG_ 2148695978 M2S_CMD2_Data3_26 "故障清除指令类型";
CM_ SG_ 2148695978 M2S_CMD2_FullChgFlgFromMBMU_26 "SOC修正指令";
CM_ SG_ 2148695978 M2S_CMD2_Data4_26 "预留";
CM_ SG_ 2148695978 M2S_MinSBMUAveTmpValue_26 "
系统温差调节参考温度";
CM_ SG_ 2148695978 M2S_CMD2_Data6_26 "预留";
CM_ SG_ 2148695978 M2S_CMD2_Data7_26 "预留";
CM_ SG_ 2148695978 M2S_CMD2_Data8_26 "预留";
CM_ SG_ 2148695979 M2S_CMD2_CRC_27 "MBMU发送给SBMU命令帧2的CRC";
CM_ SG_ 2148695979 M2S_CMD2_ALIV_27 "MBMU发送给SBMU命令帧2的生命信号，0~15循环";
CM_ SG_ 2148695979 M2S_CMD2_PowerDown_27 "MBMU发送给所有SMBU的低压下电命令";
CM_ SG_ 2148695979 M2S_CMD2_FanCtrl_27 "MBMU发送给所有SMBU的风扇控制状态";
CM_ SG_ 2148695979 M2S_CMD2_SleepCsc_27 "SBMU收到外部休眠CSC指令";
CM_ SG_ 2148695979 M2S_CMD2_Data3_27 "故障清除指令类型";
CM_ SG_ 2148695979 M2S_CMD2_FullChgFlgFromMBMU_27 "SOC修正指令";
CM_ SG_ 2148695979 M2S_CMD2_Data4_27 "预留";
CM_ SG_ 2148695979 M2S_MinSBMUAveTmpValue_27 "
系统温差调节参考温度";
CM_ SG_ 2148695979 M2S_CMD2_Data6_27 "预留";
CM_ SG_ 2148695979 M2S_CMD2_Data7_27 "预留";
CM_ SG_ 2148695979 M2S_CMD2_Data8_27 "预留";
CM_ SG_ 2148695980 M2S_CMD2_CRC_28 "MBMU发送给SBMU命令帧2的CRC";
CM_ SG_ 2148695980 M2S_CMD2_ALIV_28 "MBMU发送给SBMU命令帧2的生命信号，0~15循环";
CM_ SG_ 2148695980 M2S_CMD2_PowerDown_28 "MBMU发送给所有SMBU的低压下电命令";
CM_ SG_ 2148695980 M2S_CMD2_FanCtrl_28 "MBMU发送给所有SMBU的风扇控制状态";
CM_ SG_ 2148695980 M2S_CMD2_SleepCsc_28 "SBMU收到外部休眠CSC指令";
CM_ SG_ 2148695980 M2S_CMD2_Data3_28 "故障清除指令类型";
CM_ SG_ 2148695980 M2S_CMD2_FullChgFlgFromMBMU_28 "SOC修正指令";
CM_ SG_ 2148695980 M2S_CMD2_Data4_28 "预留";
CM_ SG_ 2148695980 M2S_MinSBMUAveTmpValue_28 "
系统温差调节参考温度";
CM_ SG_ 2148695980 M2S_CMD2_Data6_28 "预留";
CM_ SG_ 2148695980 M2S_CMD2_Data7_28 "预留";
CM_ SG_ 2148695980 M2S_CMD2_Data8_28 "预留";
CM_ SG_ 2148695981 M2S_CMD2_CRC_29 "MBMU发送给SBMU命令帧2的CRC";
CM_ SG_ 2148695981 M2S_CMD2_ALIV_29 "MBMU发送给SBMU命令帧2的生命信号，0~15循环";
CM_ SG_ 2148695981 M2S_CMD2_PowerDown_29 "MBMU发送给所有SMBU的低压下电命令";
CM_ SG_ 2148695981 M2S_CMD2_FanCtrl_29 "MBMU发送给所有SMBU的风扇控制状态";
CM_ SG_ 2148695981 M2S_CMD2_SleepCsc_29 "SBMU收到外部休眠CSC指令";
CM_ SG_ 2148695981 M2S_CMD2_Data3_29 "故障清除指令类型";
CM_ SG_ 2148695981 M2S_CMD2_FullChgFlgFromMBMU_29 "SOC修正指令";
CM_ SG_ 2148695981 M2S_CMD2_Data4_29 "预留";
CM_ SG_ 2148695981 M2S_MinSBMUAveTmpValue_29 "
系统温差调节参考温度";
CM_ SG_ 2148695981 M2S_CMD2_Data6_29 "预留";
CM_ SG_ 2148695981 M2S_CMD2_Data7_29 "预留";
CM_ SG_ 2148695981 M2S_CMD2_Data8_29 "预留";
CM_ SG_ 2148695982 M2S_CMD2_CRC_30 "MBMU发送给SBMU命令帧2的CRC";
CM_ SG_ 2148695982 M2S_CMD2_ALIV_30 "MBMU发送给SBMU命令帧2的生命信号，0~15循环";
CM_ SG_ 2148695982 M2S_CMD2_PowerDown_30 "MBMU发送给所有SMBU的低压下电命令";
CM_ SG_ 2148695982 M2S_CMD2_FanCtrl_30 "MBMU发送给所有SMBU的风扇控制状态";
CM_ SG_ 2148695982 M2S_CMD2_SleepCsc_30 "SBMU收到外部休眠CSC指令";
CM_ SG_ 2148695982 M2S_CMD2_Data3_30 "故障清除指令类型";
CM_ SG_ 2148695982 M2S_CMD2_FullChgFlgFromMBMU_30 "SOC修正指令";
CM_ SG_ 2148695982 M2S_CMD2_Data4_30 "预留";
CM_ SG_ 2148695982 M2S_MinSBMUAveTmpValue_30 "
系统温差调节参考温度";
CM_ SG_ 2148695982 M2S_CMD2_Data6_30 "预留";
CM_ SG_ 2148695982 M2S_CMD2_Data7_30 "预留";
CM_ SG_ 2148695982 M2S_CMD2_Data8_30 "预留";
CM_ SG_ 2148695983 M2S_CMD2_CRC_31 "MBMU发送给SBMU命令帧2的CRC";
CM_ SG_ 2148695983 M2S_CMD2_ALIV_31 "MBMU发送给SBMU命令帧2的生命信号，0~15循环";
CM_ SG_ 2148695983 M2S_CMD2_PowerDown_31 "MBMU发送给所有SMBU的低压下电命令";
CM_ SG_ 2148695983 M2S_CMD2_FanCtrl_31 "MBMU发送给所有SMBU的风扇控制状态";
CM_ SG_ 2148695983 M2S_CMD2_SleepCsc_31 "SBMU收到外部休眠CSC指令";
CM_ SG_ 2148695983 M2S_CMD2_Data3_31 "故障清除指令类型";
CM_ SG_ 2148695983 M2S_CMD2_FullChgFlgFromMBMU_31 "SOC修正指令";
CM_ SG_ 2148695983 M2S_CMD2_Data4_31 "预留";
CM_ SG_ 2148695983 M2S_MinSBMUAveTmpValue_31 "
系统温差调节参考温度";
CM_ SG_ 2148695983 M2S_CMD2_Data6_31 "预留";
CM_ SG_ 2148695983 M2S_CMD2_Data7_31 "预留";
CM_ SG_ 2148695983 M2S_CMD2_Data8_31 "预留";
CM_ SG_ 2148761489 M2S_CMD3_TankNo_01 "分柜号";
CM_ SG_ 2148761489 M2S_CMD3_KcFactor_01 "预留";
CM_ SG_ 2148761489 M2S_CMD3_KdFactor_01 "预留";
CM_ SG_ 2148761489 M2S_CMD3_TankSOC_01 "所有SBMU平均SOC 标定SOC值？ 确认有无实现-王刚伟
2022/10/21
wgw:没有实现";
CM_ SG_ 2148761489 M2S_CMD3_SOCCmd_01 "更新容量指令/标定SOC指令，最大，最小，显示？有无实现-王刚伟，内容
2022/10/21
wgw：没有实现";
CM_ SG_ 2148761490 M2S_CMD3_TankNo_02 "分柜号";
CM_ SG_ 2148761490 M2S_CMD3_KcFactor_02 "预留";
CM_ SG_ 2148761490 M2S_CMD3_KdFactor_02 "预留";
CM_ SG_ 2148761490 M2S_CMD3_TankSOC_02 "所有SBMU平均SOC 标定SOC值？ 确认有无实现-王刚伟
2022/10/21
wgw:没有实现";
CM_ SG_ 2148761490 M2S_CMD3_SOCCmd_02 "更新容量指令/标定SOC指令，最大，最小，显示？有无实现-王刚伟，内容
2022/10/21
wgw：没有实现";
CM_ SG_ 2148761491 M2S_CMD3_TankNo_03 "分柜号";
CM_ SG_ 2148761491 M2S_CMD3_KcFactor_03 "预留";
CM_ SG_ 2148761491 M2S_CMD3_KdFactor_03 "预留";
CM_ SG_ 2148761491 M2S_CMD3_TankSOC_03 "所有SBMU平均SOC 标定SOC值？ 确认有无实现-王刚伟
2022/10/21
wgw:没有实现";
CM_ SG_ 2148761491 M2S_CMD3_SOCCmd_03 "更新容量指令/标定SOC指令，最大，最小，显示？有无实现-王刚伟，内容
2022/10/21
wgw：没有实现";
CM_ SG_ 2148761492 M2S_CMD3_TankNo_04 "分柜号";
CM_ SG_ 2148761492 M2S_CMD3_KcFactor_04 "预留";
CM_ SG_ 2148761492 M2S_CMD3_KdFactor_04 "预留";
CM_ SG_ 2148761492 M2S_CMD3_TankSOC_04 "所有SBMU平均SOC 标定SOC值？ 确认有无实现-王刚伟
2022/10/21
wgw:没有实现";
CM_ SG_ 2148761492 M2S_CMD3_SOCCmd_04 "更新容量指令/标定SOC指令，最大，最小，显示？有无实现-王刚伟，内容
2022/10/21
wgw：没有实现";
CM_ SG_ 2148761493 M2S_CMD3_TankNo_05 "分柜号";
CM_ SG_ 2148761493 M2S_CMD3_KcFactor_05 "预留";
CM_ SG_ 2148761493 M2S_CMD3_KdFactor_05 "预留";
CM_ SG_ 2148761493 M2S_CMD3_TankSOC_05 "所有SBMU平均SOC 标定SOC值？ 确认有无实现-王刚伟
2022/10/21
wgw:没有实现";
CM_ SG_ 2148761493 M2S_CMD3_SOCCmd_05 "更新容量指令/标定SOC指令，最大，最小，显示？有无实现-王刚伟，内容
2022/10/21
wgw：没有实现";
CM_ SG_ 2148761494 M2S_CMD3_TankNo_06 "分柜号";
CM_ SG_ 2148761494 M2S_CMD3_KcFactor_06 "预留";
CM_ SG_ 2148761494 M2S_CMD3_KdFactor_06 "预留";
CM_ SG_ 2148761494 M2S_CMD3_TankSOC_06 "所有SBMU平均SOC 标定SOC值？ 确认有无实现-王刚伟
2022/10/21
wgw:没有实现";
CM_ SG_ 2148761494 M2S_CMD3_SOCCmd_06 "更新容量指令/标定SOC指令，最大，最小，显示？有无实现-王刚伟，内容
2022/10/21
wgw：没有实现";
CM_ SG_ 2148761495 M2S_CMD3_TankNo_07 "分柜号";
CM_ SG_ 2148761495 M2S_CMD3_KcFactor_07 "预留";
CM_ SG_ 2148761495 M2S_CMD3_KdFactor_07 "预留";
CM_ SG_ 2148761495 M2S_CMD3_TankSOC_07 "所有SBMU平均SOC 标定SOC值？ 确认有无实现-王刚伟
2022/10/21
wgw:没有实现";
CM_ SG_ 2148761495 M2S_CMD3_SOCCmd_07 "更新容量指令/标定SOC指令，最大，最小，显示？有无实现-王刚伟，内容
2022/10/21
wgw：没有实现";
CM_ SG_ 2148761496 M2S_CMD3_TankNo_08 "分柜号";
CM_ SG_ 2148761496 M2S_CMD3_KcFactor_08 "预留";
CM_ SG_ 2148761496 M2S_CMD3_KdFactor_08 "预留";
CM_ SG_ 2148761496 M2S_CMD3_TankSOC_08 "所有SBMU平均SOC 标定SOC值？ 确认有无实现-王刚伟
2022/10/21
wgw:没有实现";
CM_ SG_ 2148761496 M2S_CMD3_SOCCmd_08 "更新容量指令/标定SOC指令，最大，最小，显示？有无实现-王刚伟，内容
2022/10/21
wgw：没有实现";
CM_ SG_ 2148761497 M2S_CMD3_TankNo_09 "分柜号";
CM_ SG_ 2148761497 M2S_CMD3_KcFactor_09 "预留";
CM_ SG_ 2148761497 M2S_CMD3_KdFactor_09 "预留";
CM_ SG_ 2148761497 M2S_CMD3_TankSOC_09 "所有SBMU平均SOC 标定SOC值？ 确认有无实现-王刚伟
2022/10/21
wgw:没有实现";
CM_ SG_ 2148761497 M2S_CMD3_SOCCmd_09 "更新容量指令/标定SOC指令，最大，最小，显示？有无实现-王刚伟，内容
2022/10/21
wgw：没有实现";
CM_ SG_ 2148761498 M2S_CMD3_TankNo_10 "分柜号";
CM_ SG_ 2148761498 M2S_CMD3_KcFactor_10 "预留";
CM_ SG_ 2148761498 M2S_CMD3_KdFactor_10 "预留";
CM_ SG_ 2148761498 M2S_CMD3_TankSOC_10 "所有SBMU平均SOC 标定SOC值？ 确认有无实现-王刚伟
2022/10/21
wgw:没有实现";
CM_ SG_ 2148761498 M2S_CMD3_SOCCmd_10 "更新容量指令/标定SOC指令，最大，最小，显示？有无实现-王刚伟，内容
2022/10/21
wgw：没有实现";
CM_ SG_ 2148761499 M2S_CMD3_TankNo_11 "分柜号";
CM_ SG_ 2148761499 M2S_CMD3_KcFactor_11 "预留";
CM_ SG_ 2148761499 M2S_CMD3_KdFactor_11 "预留";
CM_ SG_ 2148761499 M2S_CMD3_TankSOC_11 "所有SBMU平均SOC 标定SOC值？ 确认有无实现-王刚伟
2022/10/21
wgw:没有实现";
CM_ SG_ 2148761499 M2S_CMD3_SOCCmd_11 "更新容量指令/标定SOC指令，最大，最小，显示？有无实现-王刚伟，内容
2022/10/21
wgw：没有实现";
CM_ SG_ 2148761500 M2S_CMD3_TankNo_12 "分柜号";
CM_ SG_ 2148761500 M2S_CMD3_KcFactor_12 "预留";
CM_ SG_ 2148761500 M2S_CMD3_KdFactor_12 "预留";
CM_ SG_ 2148761500 M2S_CMD3_TankSOC_12 "所有SBMU平均SOC 标定SOC值？ 确认有无实现-王刚伟
2022/10/21
wgw:没有实现";
CM_ SG_ 2148761500 M2S_CMD3_SOCCmd_12 "更新容量指令/标定SOC指令，最大，最小，显示？有无实现-王刚伟，内容
2022/10/21
wgw：没有实现";
CM_ SG_ 2148761501 M2S_CMD3_TankNo_13 "分柜号";
CM_ SG_ 2148761501 M2S_CMD3_KcFactor_13 "预留";
CM_ SG_ 2148761501 M2S_CMD3_KdFactor_13 "预留";
CM_ SG_ 2148761501 M2S_CMD3_TankSOC_13 "所有SBMU平均SOC 标定SOC值？ 确认有无实现-王刚伟
2022/10/21
wgw:没有实现";
CM_ SG_ 2148761501 M2S_CMD3_SOCCmd_13 "更新容量指令/标定SOC指令，最大，最小，显示？有无实现-王刚伟，内容
2022/10/21
wgw：没有实现";
CM_ SG_ 2148761502 M2S_CMD3_TankNo_14 "分柜号";
CM_ SG_ 2148761502 M2S_CMD3_KcFactor_14 "预留";
CM_ SG_ 2148761502 M2S_CMD3_KdFactor_14 "预留";
CM_ SG_ 2148761502 M2S_CMD3_TankSOC_14 "所有SBMU平均SOC 标定SOC值？ 确认有无实现-王刚伟
2022/10/21
wgw:没有实现";
CM_ SG_ 2148761502 M2S_CMD3_SOCCmd_14 "更新容量指令/标定SOC指令，最大，最小，显示？有无实现-王刚伟，内容
2022/10/21
wgw：没有实现";
CM_ SG_ 2148761503 M2S_CMD3_TankNo_15 "分柜号";
CM_ SG_ 2148761503 M2S_CMD3_KcFactor_15 "预留";
CM_ SG_ 2148761503 M2S_CMD3_KdFactor_15 "预留";
CM_ SG_ 2148761503 M2S_CMD3_TankSOC_15 "所有SBMU平均SOC 标定SOC值？ 确认有无实现-王刚伟
2022/10/21
wgw:没有实现";
CM_ SG_ 2148761503 M2S_CMD3_SOCCmd_15 "更新容量指令/标定SOC指令，最大，最小，显示？有无实现-王刚伟，内容
2022/10/21
wgw：没有实现";
CM_ SG_ 2148761504 M2S_CMD3_TankNo_16 "分柜号";
CM_ SG_ 2148761504 M2S_CMD3_KcFactor_16 "预留";
CM_ SG_ 2148761504 M2S_CMD3_KdFactor_16 "预留";
CM_ SG_ 2148761504 M2S_CMD3_TankSOC_16 "所有SBMU平均SOC 标定SOC值？ 确认有无实现-王刚伟
2022/10/21
wgw:没有实现";
CM_ SG_ 2148761504 M2S_CMD3_SOCCmd_16 "更新容量指令/标定SOC指令，最大，最小，显示？有无实现-王刚伟，内容
2022/10/21
wgw：没有实现";
CM_ SG_ 2148761505 M2S_CMD3_TankNo_17 "分柜号";
CM_ SG_ 2148761505 M2S_CMD3_KcFactor_17 "预留";
CM_ SG_ 2148761505 M2S_CMD3_KdFactor_17 "预留";
CM_ SG_ 2148761505 M2S_CMD3_TankSOC_17 "所有SBMU平均SOC 标定SOC值？ 确认有无实现-王刚伟
2022/10/21
wgw:没有实现";
CM_ SG_ 2148761505 M2S_CMD3_SOCCmd_17 "更新容量指令/标定SOC指令，最大，最小，显示？有无实现-王刚伟，内容
2022/10/21
wgw：没有实现";
CM_ SG_ 2148761506 M2S_CMD3_TankNo_18 "分柜号";
CM_ SG_ 2148761506 M2S_CMD3_KcFactor_18 "预留";
CM_ SG_ 2148761506 M2S_CMD3_KdFactor_18 "预留";
CM_ SG_ 2148761506 M2S_CMD3_TankSOC_18 "所有SBMU平均SOC 标定SOC值？ 确认有无实现-王刚伟
2022/10/21
wgw:没有实现";
CM_ SG_ 2148761506 M2S_CMD3_SOCCmd_18 "更新容量指令/标定SOC指令，最大，最小，显示？有无实现-王刚伟，内容
2022/10/21
wgw：没有实现";
CM_ SG_ 2148761507 M2S_CMD3_TankNo_19 "分柜号";
CM_ SG_ 2148761507 M2S_CMD3_KcFactor_19 "预留";
CM_ SG_ 2148761507 M2S_CMD3_KdFactor_19 "预留";
CM_ SG_ 2148761507 M2S_CMD3_TankSOC_19 "所有SBMU平均SOC 标定SOC值？ 确认有无实现-王刚伟
2022/10/21
wgw:没有实现";
CM_ SG_ 2148761507 M2S_CMD3_SOCCmd_19 "更新容量指令/标定SOC指令，最大，最小，显示？有无实现-王刚伟，内容
2022/10/21
wgw：没有实现";
CM_ SG_ 2148761508 M2S_CMD3_TankNo_20 "分柜号";
CM_ SG_ 2148761508 M2S_CMD3_KcFactor_20 "预留";
CM_ SG_ 2148761508 M2S_CMD3_KdFactor_20 "预留";
CM_ SG_ 2148761508 M2S_CMD3_TankSOC_20 "所有SBMU平均SOC 标定SOC值？ 确认有无实现-王刚伟
2022/10/21
wgw:没有实现";
CM_ SG_ 2148761508 M2S_CMD3_SOCCmd_20 "更新容量指令/标定SOC指令，最大，最小，显示？有无实现-王刚伟，内容
2022/10/21
wgw：没有实现";
CM_ SG_ 2148761509 M2S_CMD3_TankNo_21 "分柜号";
CM_ SG_ 2148761509 M2S_CMD3_KcFactor_21 "预留";
CM_ SG_ 2148761509 M2S_CMD3_KdFactor_21 "预留";
CM_ SG_ 2148761509 M2S_CMD3_TankSOC_21 "所有SBMU平均SOC 标定SOC值？ 确认有无实现-王刚伟
2022/10/21
wgw:没有实现";
CM_ SG_ 2148761509 M2S_CMD3_SOCCmd_21 "更新容量指令/标定SOC指令，最大，最小，显示？有无实现-王刚伟，内容
2022/10/21
wgw：没有实现";
CM_ SG_ 2148761510 M2S_CMD3_TankNo_22 "分柜号";
CM_ SG_ 2148761510 M2S_CMD3_KcFactor_22 "预留";
CM_ SG_ 2148761510 M2S_CMD3_KdFactor_22 "预留";
CM_ SG_ 2148761510 M2S_CMD3_TankSOC_22 "所有SBMU平均SOC 标定SOC值？ 确认有无实现-王刚伟
2022/10/21
wgw:没有实现";
CM_ SG_ 2148761510 M2S_CMD3_SOCCmd_22 "更新容量指令/标定SOC指令，最大，最小，显示？有无实现-王刚伟，内容
2022/10/21
wgw：没有实现";
CM_ SG_ 2148761511 M2S_CMD3_TankNo_23 "分柜号";
CM_ SG_ 2148761511 M2S_CMD3_KcFactor_23 "预留";
CM_ SG_ 2148761511 M2S_CMD3_KdFactor_23 "预留";
CM_ SG_ 2148761511 M2S_CMD3_TankSOC_23 "所有SBMU平均SOC 标定SOC值？ 确认有无实现-王刚伟
2022/10/21
wgw:没有实现";
CM_ SG_ 2148761511 M2S_CMD3_SOCCmd_23 "更新容量指令/标定SOC指令，最大，最小，显示？有无实现-王刚伟，内容
2022/10/21
wgw：没有实现";
CM_ SG_ 2148761512 M2S_CMD3_TankNo_24 "分柜号";
CM_ SG_ 2148761512 M2S_CMD3_KcFactor_24 "预留";
CM_ SG_ 2148761512 M2S_CMD3_KdFactor_24 "预留";
CM_ SG_ 2148761512 M2S_CMD3_TankSOC_24 "所有SBMU平均SOC 标定SOC值？ 确认有无实现-王刚伟
2022/10/21
wgw:没有实现";
CM_ SG_ 2148761512 M2S_CMD3_SOCCmd_24 "更新容量指令/标定SOC指令，最大，最小，显示？有无实现-王刚伟，内容
2022/10/21
wgw：没有实现";
CM_ SG_ 2148761513 M2S_CMD3_TankNo_25 "分柜号";
CM_ SG_ 2148761513 M2S_CMD3_KcFactor_25 "预留";
CM_ SG_ 2148761513 M2S_CMD3_KdFactor_25 "预留";
CM_ SG_ 2148761513 M2S_CMD3_TankSOC_25 "所有SBMU平均SOC 标定SOC值？ 确认有无实现-王刚伟
2022/10/21
wgw:没有实现";
CM_ SG_ 2148761513 M2S_CMD3_SOCCmd_25 "更新容量指令/标定SOC指令，最大，最小，显示？有无实现-王刚伟，内容
2022/10/21
wgw：没有实现";
CM_ SG_ 2148761514 M2S_CMD3_TankNo_26 "分柜号";
CM_ SG_ 2148761514 M2S_CMD3_KcFactor_26 "预留";
CM_ SG_ 2148761514 M2S_CMD3_KdFactor_26 "预留";
CM_ SG_ 2148761514 M2S_CMD3_TankSOC_26 "所有SBMU平均SOC 标定SOC值？ 确认有无实现-王刚伟
2022/10/21
wgw:没有实现";
CM_ SG_ 2148761514 M2S_CMD3_SOCCmd_26 "更新容量指令/标定SOC指令，最大，最小，显示？有无实现-王刚伟，内容
2022/10/21
wgw：没有实现";
CM_ SG_ 2148761515 M2S_CMD3_TankNo_27 "分柜号";
CM_ SG_ 2148761515 M2S_CMD3_KcFactor_27 "预留";
CM_ SG_ 2148761515 M2S_CMD3_KdFactor_27 "预留";
CM_ SG_ 2148761515 M2S_CMD3_TankSOC_27 "所有SBMU平均SOC 标定SOC值？ 确认有无实现-王刚伟
2022/10/21
wgw:没有实现";
CM_ SG_ 2148761515 M2S_CMD3_SOCCmd_27 "更新容量指令/标定SOC指令，最大，最小，显示？有无实现-王刚伟，内容
2022/10/21
wgw：没有实现";
CM_ SG_ 2148761516 M2S_CMD3_TankNo_28 "分柜号";
CM_ SG_ 2148761516 M2S_CMD3_KcFactor_28 "预留";
CM_ SG_ 2148761516 M2S_CMD3_KdFactor_28 "预留";
CM_ SG_ 2148761516 M2S_CMD3_TankSOC_28 "所有SBMU平均SOC 标定SOC值？ 确认有无实现-王刚伟
2022/10/21
wgw:没有实现";
CM_ SG_ 2148761516 M2S_CMD3_SOCCmd_28 "更新容量指令/标定SOC指令，最大，最小，显示？有无实现-王刚伟，内容
2022/10/21
wgw：没有实现";
CM_ SG_ 2148761517 M2S_CMD3_TankNo_29 "分柜号";
CM_ SG_ 2148761517 M2S_CMD3_KcFactor_29 "预留";
CM_ SG_ 2148761517 M2S_CMD3_KdFactor_29 "预留";
CM_ SG_ 2148761517 M2S_CMD3_TankSOC_29 "所有SBMU平均SOC 标定SOC值？ 确认有无实现-王刚伟
2022/10/21
wgw:没有实现";
CM_ SG_ 2148761517 M2S_CMD3_SOCCmd_29 "更新容量指令/标定SOC指令，最大，最小，显示？有无实现-王刚伟，内容
2022/10/21
wgw：没有实现";
CM_ SG_ 2148761518 M2S_CMD3_TankNo_30 "分柜号";
CM_ SG_ 2148761518 M2S_CMD3_KcFactor_30 "预留";
CM_ SG_ 2148761518 M2S_CMD3_KdFactor_30 "预留";
CM_ SG_ 2148761518 M2S_CMD3_TankSOC_30 "所有SBMU平均SOC 标定SOC值？ 确认有无实现-王刚伟
2022/10/21
wgw:没有实现";
CM_ SG_ 2148761518 M2S_CMD3_SOCCmd_30 "更新容量指令/标定SOC指令，最大，最小，显示？有无实现-王刚伟，内容
2022/10/21
wgw：没有实现";
CM_ SG_ 2148761519 M2S_CMD3_TankNo_31 "分柜号";
CM_ SG_ 2148761519 M2S_CMD3_KcFactor_31 "预留";
CM_ SG_ 2148761519 M2S_CMD3_KdFactor_31 "预留";
CM_ SG_ 2148761519 M2S_CMD3_TankSOC_31 "所有SBMU平均SOC 标定SOC值？ 确认有无实现-王刚伟
2022/10/21
wgw:没有实现";
CM_ SG_ 2148761519 M2S_CMD3_SOCCmd_31 "更新容量指令/标定SOC指令，最大，最小，显示？有无实现-王刚伟，内容
2022/10/21
wgw：没有实现";
CM_ SG_ 2265050769 M2P_AL_Fault_Page_01 "故障码页";
CM_ SG_ 2265050769 M2P_AL_Fault_Number1_01 "故障码1";
CM_ SG_ 2265050769 M2P_AL_Fault_Number2_01 "故障码2";
CM_ SG_ 2265050769 M2P_AL_Fault_Number3_01 "故障码3";
CM_ SG_ 2265050769 M2P_AL_Fault_Number4_01 "故障码4";
CM_ SG_ 2265050769 M2P_AL_Fault_Number5_01 "故障码5";
CM_ SG_ 2265050769 M2P_AL_Fault_Number6_01 "故障码6";
CM_ SG_ 2265050770 M2P_AL_Fault_Page_02 "故障码页";
CM_ SG_ 2265050770 M2P_AL_Fault_Number1_02 "故障码1";
CM_ SG_ 2265050770 M2P_AL_Fault_Number2_02 "故障码2";
CM_ SG_ 2265050770 M2P_AL_Fault_Number3_02 "故障码3";
CM_ SG_ 2265050770 M2P_AL_Fault_Number4_02 "故障码4";
CM_ SG_ 2265050770 M2P_AL_Fault_Number5_02 "故障码5";
CM_ SG_ 2265050770 M2P_AL_Fault_Number6_02 "故障码6";
CM_ SG_ 2265050771 M2P_AL_Fault_Page_03 "故障码页";
CM_ SG_ 2265050771 M2P_AL_Fault_Number1_03 "故障码1";
CM_ SG_ 2265050771 M2P_AL_Fault_Number2_03 "故障码2";
CM_ SG_ 2265050771 M2P_AL_Fault_Number3_03 "故障码3";
CM_ SG_ 2265050771 M2P_AL_Fault_Number4_03 "故障码4";
CM_ SG_ 2265050771 M2P_AL_Fault_Number5_03 "故障码5";
CM_ SG_ 2265050771 M2P_AL_Fault_Number6_03 "故障码6";
CM_ SG_ 2265050772 M2P_AL_Fault_Page_04 "故障码页";
CM_ SG_ 2265050772 M2P_AL_Fault_Number1_04 "故障码1";
CM_ SG_ 2265050772 M2P_AL_Fault_Number2_04 "故障码2";
CM_ SG_ 2265050772 M2P_AL_Fault_Number3_04 "故障码3";
CM_ SG_ 2265050772 M2P_AL_Fault_Number4_04 "故障码4";
CM_ SG_ 2265050772 M2P_AL_Fault_Number5_04 "故障码5";
CM_ SG_ 2265050772 M2P_AL_Fault_Number6_04 "故障码6";
CM_ SG_ 2265050773 M2P_AL_Fault_Page_05 "故障码页";
CM_ SG_ 2265050773 M2P_AL_Fault_Number1_05 "故障码1";
CM_ SG_ 2265050773 M2P_AL_Fault_Number2_05 "故障码2";
CM_ SG_ 2265050773 M2P_AL_Fault_Number3_05 "故障码3";
CM_ SG_ 2265050773 M2P_AL_Fault_Number4_05 "故障码4";
CM_ SG_ 2265050773 M2P_AL_Fault_Number5_05 "故障码5";
CM_ SG_ 2265050773 M2P_AL_Fault_Number6_05 "故障码6";
CM_ SG_ 2265050774 M2P_AL_Fault_Page_06 "故障码页";
CM_ SG_ 2265050774 M2P_AL_Fault_Number1_06 "故障码1";
CM_ SG_ 2265050774 M2P_AL_Fault_Number2_06 "故障码2";
CM_ SG_ 2265050774 M2P_AL_Fault_Number3_06 "故障码3";
CM_ SG_ 2265050774 M2P_AL_Fault_Number4_06 "故障码4";
CM_ SG_ 2265050774 M2P_AL_Fault_Number5_06 "故障码5";
CM_ SG_ 2265050774 M2P_AL_Fault_Number6_06 "故障码6";
CM_ SG_ 2265050775 M2P_AL_Fault_Page_07 "故障码页";
CM_ SG_ 2265050775 M2P_AL_Fault_Number1_07 "故障码1";
CM_ SG_ 2265050775 M2P_AL_Fault_Number2_07 "故障码2";
CM_ SG_ 2265050775 M2P_AL_Fault_Number3_07 "故障码3";
CM_ SG_ 2265050775 M2P_AL_Fault_Number4_07 "故障码4";
CM_ SG_ 2265050775 M2P_AL_Fault_Number5_07 "故障码5";
CM_ SG_ 2265050775 M2P_AL_Fault_Number6_07 "故障码6";
CM_ SG_ 2265050776 M2P_AL_Fault_Page_08 "故障码页";
CM_ SG_ 2265050776 M2P_AL_Fault_Number1_08 "故障码1";
CM_ SG_ 2265050776 M2P_AL_Fault_Number2_08 "故障码2";
CM_ SG_ 2265050776 M2P_AL_Fault_Number3_08 "故障码3";
CM_ SG_ 2265050776 M2P_AL_Fault_Number4_08 "故障码4";
CM_ SG_ 2265050776 M2P_AL_Fault_Number5_08 "故障码5";
CM_ SG_ 2265050776 M2P_AL_Fault_Number6_08 "故障码6";
CM_ SG_ 2265050777 M2P_AL_Fault_Page_09 "故障码页";
CM_ SG_ 2265050777 M2P_AL_Fault_Number1_09 "故障码1";
CM_ SG_ 2265050777 M2P_AL_Fault_Number2_09 "故障码2";
CM_ SG_ 2265050777 M2P_AL_Fault_Number3_09 "故障码3";
CM_ SG_ 2265050777 M2P_AL_Fault_Number4_09 "故障码4";
CM_ SG_ 2265050777 M2P_AL_Fault_Number5_09 "故障码5";
CM_ SG_ 2265050777 M2P_AL_Fault_Number6_09 "故障码6";
CM_ SG_ 2265050778 M2P_AL_Fault_Page_10 "故障码页";
CM_ SG_ 2265050778 M2P_AL_Fault_Number1_10 "故障码1";
CM_ SG_ 2265050778 M2P_AL_Fault_Number2_10 "故障码2";
CM_ SG_ 2265050778 M2P_AL_Fault_Number3_10 "故障码3";
CM_ SG_ 2265050778 M2P_AL_Fault_Number4_10 "故障码4";
CM_ SG_ 2265050778 M2P_AL_Fault_Number5_10 "故障码5";
CM_ SG_ 2265050778 M2P_AL_Fault_Number6_10 "故障码6";
CM_ SG_ 2265050779 M2P_AL_Fault_Page_11 "故障码页";
CM_ SG_ 2265050779 M2P_AL_Fault_Number1_11 "故障码1";
CM_ SG_ 2265050779 M2P_AL_Fault_Number2_11 "故障码2";
CM_ SG_ 2265050779 M2P_AL_Fault_Number3_11 "故障码3";
CM_ SG_ 2265050779 M2P_AL_Fault_Number4_11 "故障码4";
CM_ SG_ 2265050779 M2P_AL_Fault_Number5_11 "故障码5";
CM_ SG_ 2265050779 M2P_AL_Fault_Number6_11 "故障码6";
CM_ SG_ 2265050780 M2P_AL_Fault_Page_12 "故障码页";
CM_ SG_ 2265050780 M2P_AL_Fault_Number1_12 "故障码1";
CM_ SG_ 2265050780 M2P_AL_Fault_Number2_12 "故障码2";
CM_ SG_ 2265050780 M2P_AL_Fault_Number3_12 "故障码3";
CM_ SG_ 2265050780 M2P_AL_Fault_Number4_12 "故障码4";
CM_ SG_ 2265050780 M2P_AL_Fault_Number5_12 "故障码5";
CM_ SG_ 2265050780 M2P_AL_Fault_Number6_12 "故障码6";
VAL_ 2148630433 HvPwrOnCmd_SBMU01_17 0 "请求正常下高压" 1 "请求上高压" 2 "强制SBMU下高压" ;
VAL_ 2148630433 HvPwrOnCmd_SBMU02_17 0 "请求正常下高压" 1 "请求上高压" 2 "强制SBMU下高压" ;
VAL_ 2148630433 HvPwrOnCmd_SBMU03_17 0 "请求正常下高压" 1 "请求上高压" 2 "强制SBMU下高压" ;
VAL_ 2148630433 HvPwrOnCmd_SBMU04_17 0 "请求正常下高压" 1 "请求上高压" 2 "强制SBMU下高压" ;
VAL_ 2148630433 HvPwrOnCmd_SBMU05_17 0 "请求正常下高压" 1 "请求上高压" 2 "强制SBMU下高压" ;
VAL_ 2148630433 HvPwrOnCmd_SBMU06_17 0 "请求正常下高压" 1 "请求上高压" 2 "强制SBMU下高压" ;
VAL_ 2148630433 HvPwrOnCmd_SBMU07_17 0 "请求正常下高压" 1 "请求上高压" 2 "强制SBMU下高压" ;
VAL_ 2148630433 HvPwrOnCmd_SBMU08_17 0 "请求正常下高压" 1 "请求上高压" 2 "强制SBMU下高压" ;
VAL_ 2148630433 HvPwrOnCmd_SBMU09_17 0 "请求正常下高压" 1 "请求上高压" 2 "强制SBMU下高压" ;
VAL_ 2148630433 HvPwrOnCmd_SBMU10_17 0 "请求正常下高压" 1 "请求上高压" 2 "强制SBMU下高压" ;
VAL_ 2148630433 HvPwrOnCmd_SBMU11_17 0 "请求正常下高压" 1 "请求上高压" 2 "强制SBMU下高压" ;
VAL_ 2148630433 HvPwrOnCmd_SBMU12_17 0 "请求正常下高压" 1 "请求上高压" 2 "强制SBMU下高压" ;
VAL_ 2148630433 HvPwrOnCmd_SBMU13_17 0 "请求正常下高压" 1 "请求上高压" 2 "强制SBMU下高压" ;
VAL_ 2148630433 HvPwrOnCmd_SBMU14_17 0 "请求正常下高压" 1 "请求上高压" 2 "强制SBMU下高压" ;
VAL_ 2148630433 HvPwrOnCmd_SBMU15_17 0 "请求正常下高压" 1 "请求上高压" 2 "强制SBMU下高压" ;
VAL_ 2148630433 HvPwrOnCmd_SBMU16_17 0 "请求正常下高压" 1 "请求上高压" 2 "强制SBMU下高压" ;
VAL_ 2148630433 HvPwrOnCmd_SBMU17_17 0 "请求正常下高压" 1 "请求上高压" 2 "强制SBMU下高压" ;
VAL_ 2148630433 HvPwrOnCmd_SBMU18_17 0 "请求正常下高压" 1 "请求上高压" 2 "强制SBMU下高压" ;
VAL_ 2148630433 HvPwrOnCmd_SBMU19_17 0 "请求正常下高压" 1 "请求上高压" 2 "强制SBMU下高压" ;
VAL_ 2148630433 HvPwrOnCmd_SBMU20_17 0 "请求正常下高压" 1 "请求上高压" 2 "强制SBMU下高压" ;
VAL_ 2148630433 HvPwrOnCmd_SBMU21_17 0 "请求正常下高压" 1 "请求上高压" 2 "强制SBMU下高压" ;
VAL_ 2148630433 HvPwrOnCmd_SBMU22_17 0 "请求正常下高压" 1 "请求上高压" 2 "强制SBMU下高压" ;
VAL_ 2148630433 HvPwrOnCmd_SBMU23_17 0 "请求正常下高压" 1 "请求上高压" 2 "强制SBMU下高压" ;
VAL_ 2148630433 HvPwrOnCmd_SBMU24_17 0 "请求正常下高压" 1 "请求上高压" 2 "强制SBMU下高压" ;
VAL_ 2148630433 HvPwrOnCmd_SBMU25_17 0 "请求正常下高压" 1 "请求上高压" 2 "强制SBMU下高压" ;
VAL_ 2148630433 HvPwrOnCmd_SBMU26_17 0 "请求正常下高压" 1 "请求上高压" 2 "强制SBMU下高压" ;
VAL_ 2148630433 HvPwrOnCmd_SBMU27_17 0 "请求正常下高压" 1 "请求上高压" 2 "强制SBMU下高压" ;
VAL_ 2148630433 HvPwrOnCmd_SBMU28_17 0 "请求正常下高压" 1 "请求上高压" 2 "强制SBMU下高压" ;
VAL_ 2148630433 HvPwrOnCmd_SBMU29_17 0 "请求正常下高压" 1 "请求上高压" 2 "强制SBMU下高压" ;
VAL_ 2148630433 HvPwrOnCmd_SBMU30_17 0 "请求正常下高压" 1 "请求上高压" 2 "强制SBMU下高压" ;
VAL_ 2148630433 HvPwrOnCmd_SBMU31_17 0 "请求正常下高压" 1 "请求上高压" 2 "强制SBMU下高压" ;
VAL_ 2148630433 HvPwrOnCmd_SBMU32_17 0 "请求正常下高压" 1 "请求上高压" 2 "强制SBMU下高压" ;
VAL_ 2148630434 HvPwrOnCmd_SBMU01_18 0 "请求正常下高压" 1 "请求上高压" 2 "强制SBMU下高压" ;
VAL_ 2148630434 HvPwrOnCmd_SBMU02_18 0 "请求正常下高压" 1 "请求上高压" 2 "强制SBMU下高压" ;
VAL_ 2148630434 HvPwrOnCmd_SBMU03_18 0 "请求正常下高压" 1 "请求上高压" 2 "强制SBMU下高压" ;
VAL_ 2148630434 HvPwrOnCmd_SBMU04_18 0 "请求正常下高压" 1 "请求上高压" 2 "强制SBMU下高压" ;
VAL_ 2148630434 HvPwrOnCmd_SBMU05_18 0 "请求正常下高压" 1 "请求上高压" 2 "强制SBMU下高压" ;
VAL_ 2148630434 HvPwrOnCmd_SBMU06_18 0 "请求正常下高压" 1 "请求上高压" 2 "强制SBMU下高压" ;
VAL_ 2148630434 HvPwrOnCmd_SBMU07_18 0 "请求正常下高压" 1 "请求上高压" 2 "强制SBMU下高压" ;
VAL_ 2148630434 HvPwrOnCmd_SBMU08_18 0 "请求正常下高压" 1 "请求上高压" 2 "强制SBMU下高压" ;
VAL_ 2148630434 HvPwrOnCmd_SBMU09_18 0 "请求正常下高压" 1 "请求上高压" 2 "强制SBMU下高压" ;
VAL_ 2148630434 HvPwrOnCmd_SBMU10_18 0 "请求正常下高压" 1 "请求上高压" 2 "强制SBMU下高压" ;
VAL_ 2148630434 HvPwrOnCmd_SBMU11_18 0 "请求正常下高压" 1 "请求上高压" 2 "强制SBMU下高压" ;
VAL_ 2148630434 HvPwrOnCmd_SBMU12_18 0 "请求正常下高压" 1 "请求上高压" 2 "强制SBMU下高压" ;
VAL_ 2148630434 HvPwrOnCmd_SBMU13_18 0 "请求正常下高压" 1 "请求上高压" 2 "强制SBMU下高压" ;
VAL_ 2148630434 HvPwrOnCmd_SBMU14_18 0 "请求正常下高压" 1 "请求上高压" 2 "强制SBMU下高压" ;
VAL_ 2148630434 HvPwrOnCmd_SBMU15_18 0 "请求正常下高压" 1 "请求上高压" 2 "强制SBMU下高压" ;
VAL_ 2148630434 HvPwrOnCmd_SBMU16_18 0 "请求正常下高压" 1 "请求上高压" 2 "强制SBMU下高压" ;
VAL_ 2148630434 HvPwrOnCmd_SBMU17_18 0 "请求正常下高压" 1 "请求上高压" 2 "强制SBMU下高压" ;
VAL_ 2148630434 HvPwrOnCmd_SBMU18_18 0 "请求正常下高压" 1 "请求上高压" 2 "强制SBMU下高压" ;
VAL_ 2148630434 HvPwrOnCmd_SBMU19_18 0 "请求正常下高压" 1 "请求上高压" 2 "强制SBMU下高压" ;
VAL_ 2148630434 HvPwrOnCmd_SBMU20_18 0 "请求正常下高压" 1 "请求上高压" 2 "强制SBMU下高压" ;
VAL_ 2148630434 HvPwrOnCmd_SBMU21_18 0 "请求正常下高压" 1 "请求上高压" 2 "强制SBMU下高压" ;
VAL_ 2148630434 HvPwrOnCmd_SBMU22_18 0 "请求正常下高压" 1 "请求上高压" 2 "强制SBMU下高压" ;
VAL_ 2148630434 HvPwrOnCmd_SBMU23_18 0 "请求正常下高压" 1 "请求上高压" 2 "强制SBMU下高压" ;
VAL_ 2148630434 HvPwrOnCmd_SBMU24_18 0 "请求正常下高压" 1 "请求上高压" 2 "强制SBMU下高压" ;
VAL_ 2148630434 HvPwrOnCmd_SBMU25_18 0 "请求正常下高压" 1 "请求上高压" 2 "强制SBMU下高压" ;
VAL_ 2148630434 HvPwrOnCmd_SBMU26_18 0 "请求正常下高压" 1 "请求上高压" 2 "强制SBMU下高压" ;
VAL_ 2148630434 HvPwrOnCmd_SBMU27_18 0 "请求正常下高压" 1 "请求上高压" 2 "强制SBMU下高压" ;
VAL_ 2148630434 HvPwrOnCmd_SBMU28_18 0 "请求正常下高压" 1 "请求上高压" 2 "强制SBMU下高压" ;
VAL_ 2148630434 HvPwrOnCmd_SBMU29_18 0 "请求正常下高压" 1 "请求上高压" 2 "强制SBMU下高压" ;
VAL_ 2148630434 HvPwrOnCmd_SBMU30_18 0 "请求正常下高压" 1 "请求上高压" 2 "强制SBMU下高压" ;
VAL_ 2148630434 HvPwrOnCmd_SBMU31_18 0 "请求正常下高压" 1 "请求上高压" 2 "强制SBMU下高压" ;
VAL_ 2148630434 HvPwrOnCmd_SBMU32_18 0 "请求正常下高压" 1 "请求上高压" 2 "强制SBMU下高压" ;
VAL_ 2148630435 HvPwrOnCmd_SBMU01_19 0 "请求正常下高压" 1 "请求上高压" 2 "强制SBMU下高压" ;
VAL_ 2148630435 HvPwrOnCmd_SBMU02_19 0 "请求正常下高压" 1 "请求上高压" 2 "强制SBMU下高压" ;
VAL_ 2148630435 HvPwrOnCmd_SBMU03_19 0 "请求正常下高压" 1 "请求上高压" 2 "强制SBMU下高压" ;
VAL_ 2148630435 HvPwrOnCmd_SBMU04_19 0 "请求正常下高压" 1 "请求上高压" 2 "强制SBMU下高压" ;
VAL_ 2148630435 HvPwrOnCmd_SBMU05_19 0 "请求正常下高压" 1 "请求上高压" 2 "强制SBMU下高压" ;
VAL_ 2148630435 HvPwrOnCmd_SBMU06_19 0 "请求正常下高压" 1 "请求上高压" 2 "强制SBMU下高压" ;
VAL_ 2148630435 HvPwrOnCmd_SBMU07_19 0 "请求正常下高压" 1 "请求上高压" 2 "强制SBMU下高压" ;
VAL_ 2148630435 HvPwrOnCmd_SBMU08_19 0 "请求正常下高压" 1 "请求上高压" 2 "强制SBMU下高压" ;
VAL_ 2148630435 HvPwrOnCmd_SBMU09_19 0 "请求正常下高压" 1 "请求上高压" 2 "强制SBMU下高压" ;
VAL_ 2148630435 HvPwrOnCmd_SBMU10_19 0 "请求正常下高压" 1 "请求上高压" 2 "强制SBMU下高压" ;
VAL_ 2148630435 HvPwrOnCmd_SBMU11_19 0 "请求正常下高压" 1 "请求上高压" 2 "强制SBMU下高压" ;
VAL_ 2148630435 HvPwrOnCmd_SBMU12_19 0 "请求正常下高压" 1 "请求上高压" 2 "强制SBMU下高压" ;
VAL_ 2148630435 HvPwrOnCmd_SBMU13_19 0 "请求正常下高压" 1 "请求上高压" 2 "强制SBMU下高压" ;
VAL_ 2148630435 HvPwrOnCmd_SBMU14_19 0 "请求正常下高压" 1 "请求上高压" 2 "强制SBMU下高压" ;
VAL_ 2148630435 HvPwrOnCmd_SBMU15_19 0 "请求正常下高压" 1 "请求上高压" 2 "强制SBMU下高压" ;
VAL_ 2148630435 HvPwrOnCmd_SBMU16_19 0 "请求正常下高压" 1 "请求上高压" 2 "强制SBMU下高压" ;
VAL_ 2148630435 HvPwrOnCmd_SBMU17_19 0 "请求正常下高压" 1 "请求上高压" 2 "强制SBMU下高压" ;
VAL_ 2148630435 HvPwrOnCmd_SBMU18_19 0 "请求正常下高压" 1 "请求上高压" 2 "强制SBMU下高压" ;
VAL_ 2148630435 HvPwrOnCmd_SBMU19_19 0 "请求正常下高压" 1 "请求上高压" 2 "强制SBMU下高压" ;
VAL_ 2148630435 HvPwrOnCmd_SBMU20_19 0 "请求正常下高压" 1 "请求上高压" 2 "强制SBMU下高压" ;
VAL_ 2148630435 HvPwrOnCmd_SBMU21_19 0 "请求正常下高压" 1 "请求上高压" 2 "强制SBMU下高压" ;
VAL_ 2148630435 HvPwrOnCmd_SBMU22_19 0 "请求正常下高压" 1 "请求上高压" 2 "强制SBMU下高压" ;
VAL_ 2148630435 HvPwrOnCmd_SBMU23_19 0 "请求正常下高压" 1 "请求上高压" 2 "强制SBMU下高压" ;
VAL_ 2148630435 HvPwrOnCmd_SBMU24_19 0 "请求正常下高压" 1 "请求上高压" 2 "强制SBMU下高压" ;
VAL_ 2148630435 HvPwrOnCmd_SBMU25_19 0 "请求正常下高压" 1 "请求上高压" 2 "强制SBMU下高压" ;
VAL_ 2148630435 HvPwrOnCmd_SBMU26_19 0 "请求正常下高压" 1 "请求上高压" 2 "强制SBMU下高压" ;
VAL_ 2148630435 HvPwrOnCmd_SBMU27_19 0 "请求正常下高压" 1 "请求上高压" 2 "强制SBMU下高压" ;
VAL_ 2148630435 HvPwrOnCmd_SBMU28_19 0 "请求正常下高压" 1 "请求上高压" 2 "强制SBMU下高压" ;
VAL_ 2148630435 HvPwrOnCmd_SBMU29_19 0 "请求正常下高压" 1 "请求上高压" 2 "强制SBMU下高压" ;
VAL_ 2148630435 HvPwrOnCmd_SBMU30_19 0 "请求正常下高压" 1 "请求上高压" 2 "强制SBMU下高压" ;
VAL_ 2148630435 HvPwrOnCmd_SBMU31_19 0 "请求正常下高压" 1 "请求上高压" 2 "强制SBMU下高压" ;
VAL_ 2148630435 HvPwrOnCmd_SBMU32_19 0 "请求正常下高压" 1 "请求上高压" 2 "强制SBMU下高压" ;
VAL_ 2148630436 HvPwrOnCmd_SBMU01_20 0 "请求正常下高压" 1 "请求上高压" 2 "强制SBMU下高压" ;
VAL_ 2148630436 HvPwrOnCmd_SBMU02_20 0 "请求正常下高压" 1 "请求上高压" 2 "强制SBMU下高压" ;
VAL_ 2148630436 HvPwrOnCmd_SBMU03_20 0 "请求正常下高压" 1 "请求上高压" 2 "强制SBMU下高压" ;
VAL_ 2148630436 HvPwrOnCmd_SBMU04_20 0 "请求正常下高压" 1 "请求上高压" 2 "强制SBMU下高压" ;
VAL_ 2148630436 HvPwrOnCmd_SBMU05_20 0 "请求正常下高压" 1 "请求上高压" 2 "强制SBMU下高压" ;
VAL_ 2148630436 HvPwrOnCmd_SBMU06_20 0 "请求正常下高压" 1 "请求上高压" 2 "强制SBMU下高压" ;
VAL_ 2148630436 HvPwrOnCmd_SBMU07_20 0 "请求正常下高压" 1 "请求上高压" 2 "强制SBMU下高压" ;
VAL_ 2148630436 HvPwrOnCmd_SBMU08_20 0 "请求正常下高压" 1 "请求上高压" 2 "强制SBMU下高压" ;
VAL_ 2148630436 HvPwrOnCmd_SBMU09_20 0 "请求正常下高压" 1 "请求上高压" 2 "强制SBMU下高压" ;
VAL_ 2148630436 HvPwrOnCmd_SBMU10_20 0 "请求正常下高压" 1 "请求上高压" 2 "强制SBMU下高压" ;
VAL_ 2148630436 HvPwrOnCmd_SBMU11_20 0 "请求正常下高压" 1 "请求上高压" 2 "强制SBMU下高压" ;
VAL_ 2148630436 HvPwrOnCmd_SBMU12_20 0 "请求正常下高压" 1 "请求上高压" 2 "强制SBMU下高压" ;
VAL_ 2148630436 HvPwrOnCmd_SBMU13_20 0 "请求正常下高压" 1 "请求上高压" 2 "强制SBMU下高压" ;
VAL_ 2148630436 HvPwrOnCmd_SBMU14_20 0 "请求正常下高压" 1 "请求上高压" 2 "强制SBMU下高压" ;
VAL_ 2148630436 HvPwrOnCmd_SBMU15_20 0 "请求正常下高压" 1 "请求上高压" 2 "强制SBMU下高压" ;
VAL_ 2148630436 HvPwrOnCmd_SBMU16_20 0 "请求正常下高压" 1 "请求上高压" 2 "强制SBMU下高压" ;
VAL_ 2148630436 HvPwrOnCmd_SBMU17_20 0 "请求正常下高压" 1 "请求上高压" 2 "强制SBMU下高压" ;
VAL_ 2148630436 HvPwrOnCmd_SBMU18_20 0 "请求正常下高压" 1 "请求上高压" 2 "强制SBMU下高压" ;
VAL_ 2148630436 HvPwrOnCmd_SBMU19_20 0 "请求正常下高压" 1 "请求上高压" 2 "强制SBMU下高压" ;
VAL_ 2148630436 HvPwrOnCmd_SBMU20_20 0 "请求正常下高压" 1 "请求上高压" 2 "强制SBMU下高压" ;
VAL_ 2148630436 HvPwrOnCmd_SBMU21_20 0 "请求正常下高压" 1 "请求上高压" 2 "强制SBMU下高压" ;
VAL_ 2148630436 HvPwrOnCmd_SBMU22_20 0 "请求正常下高压" 1 "请求上高压" 2 "强制SBMU下高压" ;
VAL_ 2148630436 HvPwrOnCmd_SBMU23_20 0 "请求正常下高压" 1 "请求上高压" 2 "强制SBMU下高压" ;
VAL_ 2148630436 HvPwrOnCmd_SBMU24_20 0 "请求正常下高压" 1 "请求上高压" 2 "强制SBMU下高压" ;
VAL_ 2148630436 HvPwrOnCmd_SBMU25_20 0 "请求正常下高压" 1 "请求上高压" 2 "强制SBMU下高压" ;
VAL_ 2148630436 HvPwrOnCmd_SBMU26_20 0 "请求正常下高压" 1 "请求上高压" 2 "强制SBMU下高压" ;
VAL_ 2148630436 HvPwrOnCmd_SBMU27_20 0 "请求正常下高压" 1 "请求上高压" 2 "强制SBMU下高压" ;
VAL_ 2148630436 HvPwrOnCmd_SBMU28_20 0 "请求正常下高压" 1 "请求上高压" 2 "强制SBMU下高压" ;
VAL_ 2148630436 HvPwrOnCmd_SBMU29_20 0 "请求正常下高压" 1 "请求上高压" 2 "强制SBMU下高压" ;
VAL_ 2148630436 HvPwrOnCmd_SBMU30_20 0 "请求正常下高压" 1 "请求上高压" 2 "强制SBMU下高压" ;
VAL_ 2148630436 HvPwrOnCmd_SBMU31_20 0 "请求正常下高压" 1 "请求上高压" 2 "强制SBMU下高压" ;
VAL_ 2148630436 HvPwrOnCmd_SBMU32_20 0 "请求正常下高压" 1 "请求上高压" 2 "强制SBMU下高压" ;
VAL_ 2148630437 HvPwrOnCmd_SBMU01_21 0 "请求正常下高压" 1 "请求上高压" 2 "强制SBMU下高压" ;
VAL_ 2148630437 HvPwrOnCmd_SBMU02_21 0 "请求正常下高压" 1 "请求上高压" 2 "强制SBMU下高压" ;
VAL_ 2148630437 HvPwrOnCmd_SBMU03_21 0 "请求正常下高压" 1 "请求上高压" 2 "强制SBMU下高压" ;
VAL_ 2148630437 HvPwrOnCmd_SBMU04_21 0 "请求正常下高压" 1 "请求上高压" 2 "强制SBMU下高压" ;
VAL_ 2148630437 HvPwrOnCmd_SBMU05_21 0 "请求正常下高压" 1 "请求上高压" 2 "强制SBMU下高压" ;
VAL_ 2148630437 HvPwrOnCmd_SBMU06_21 0 "请求正常下高压" 1 "请求上高压" 2 "强制SBMU下高压" ;
VAL_ 2148630437 HvPwrOnCmd_SBMU07_21 0 "请求正常下高压" 1 "请求上高压" 2 "强制SBMU下高压" ;
VAL_ 2148630437 HvPwrOnCmd_SBMU08_21 0 "请求正常下高压" 1 "请求上高压" 2 "强制SBMU下高压" ;
VAL_ 2148630437 HvPwrOnCmd_SBMU09_21 0 "请求正常下高压" 1 "请求上高压" 2 "强制SBMU下高压" ;
VAL_ 2148630437 HvPwrOnCmd_SBMU10_21 0 "请求正常下高压" 1 "请求上高压" 2 "强制SBMU下高压" ;
VAL_ 2148630437 HvPwrOnCmd_SBMU11_21 0 "请求正常下高压" 1 "请求上高压" 2 "强制SBMU下高压" ;
VAL_ 2148630437 HvPwrOnCmd_SBMU12_21 0 "请求正常下高压" 1 "请求上高压" 2 "强制SBMU下高压" ;
VAL_ 2148630437 HvPwrOnCmd_SBMU13_21 0 "请求正常下高压" 1 "请求上高压" 2 "强制SBMU下高压" ;
VAL_ 2148630437 HvPwrOnCmd_SBMU14_21 0 "请求正常下高压" 1 "请求上高压" 2 "强制SBMU下高压" ;
VAL_ 2148630437 HvPwrOnCmd_SBMU15_21 0 "请求正常下高压" 1 "请求上高压" 2 "强制SBMU下高压" ;
VAL_ 2148630437 HvPwrOnCmd_SBMU16_21 0 "请求正常下高压" 1 "请求上高压" 2 "强制SBMU下高压" ;
VAL_ 2148630437 HvPwrOnCmd_SBMU17_21 0 "请求正常下高压" 1 "请求上高压" 2 "强制SBMU下高压" ;
VAL_ 2148630437 HvPwrOnCmd_SBMU18_21 0 "请求正常下高压" 1 "请求上高压" 2 "强制SBMU下高压" ;
VAL_ 2148630437 HvPwrOnCmd_SBMU19_21 0 "请求正常下高压" 1 "请求上高压" 2 "强制SBMU下高压" ;
VAL_ 2148630437 HvPwrOnCmd_SBMU20_21 0 "请求正常下高压" 1 "请求上高压" 2 "强制SBMU下高压" ;
VAL_ 2148630437 HvPwrOnCmd_SBMU21_21 0 "请求正常下高压" 1 "请求上高压" 2 "强制SBMU下高压" ;
VAL_ 2148630437 HvPwrOnCmd_SBMU22_21 0 "请求正常下高压" 1 "请求上高压" 2 "强制SBMU下高压" ;
VAL_ 2148630437 HvPwrOnCmd_SBMU23_21 0 "请求正常下高压" 1 "请求上高压" 2 "强制SBMU下高压" ;
VAL_ 2148630437 HvPwrOnCmd_SBMU24_21 0 "请求正常下高压" 1 "请求上高压" 2 "强制SBMU下高压" ;
VAL_ 2148630437 HvPwrOnCmd_SBMU25_21 0 "请求正常下高压" 1 "请求上高压" 2 "强制SBMU下高压" ;
VAL_ 2148630437 HvPwrOnCmd_SBMU26_21 0 "请求正常下高压" 1 "请求上高压" 2 "强制SBMU下高压" ;
VAL_ 2148630437 HvPwrOnCmd_SBMU27_21 0 "请求正常下高压" 1 "请求上高压" 2 "强制SBMU下高压" ;
VAL_ 2148630437 HvPwrOnCmd_SBMU28_21 0 "请求正常下高压" 1 "请求上高压" 2 "强制SBMU下高压" ;
VAL_ 2148630437 HvPwrOnCmd_SBMU29_21 0 "请求正常下高压" 1 "请求上高压" 2 "强制SBMU下高压" ;
VAL_ 2148630437 HvPwrOnCmd_SBMU30_21 0 "请求正常下高压" 1 "请求上高压" 2 "强制SBMU下高压" ;
VAL_ 2148630437 HvPwrOnCmd_SBMU31_21 0 "请求正常下高压" 1 "请求上高压" 2 "强制SBMU下高压" ;
VAL_ 2148630437 HvPwrOnCmd_SBMU32_21 0 "请求正常下高压" 1 "请求上高压" 2 "强制SBMU下高压" ;
VAL_ 2148630438 HvPwrOnCmd_SBMU01_22 0 "请求正常下高压" 1 "请求上高压" 2 "强制SBMU下高压" ;
VAL_ 2148630438 HvPwrOnCmd_SBMU02_22 0 "请求正常下高压" 1 "请求上高压" 2 "强制SBMU下高压" ;
VAL_ 2148630438 HvPwrOnCmd_SBMU03_22 0 "请求正常下高压" 1 "请求上高压" 2 "强制SBMU下高压" ;
VAL_ 2148630438 HvPwrOnCmd_SBMU04_22 0 "请求正常下高压" 1 "请求上高压" 2 "强制SBMU下高压" ;
VAL_ 2148630438 HvPwrOnCmd_SBMU05_22 0 "请求正常下高压" 1 "请求上高压" 2 "强制SBMU下高压" ;
VAL_ 2148630438 HvPwrOnCmd_SBMU06_22 0 "请求正常下高压" 1 "请求上高压" 2 "强制SBMU下高压" ;
VAL_ 2148630438 HvPwrOnCmd_SBMU07_22 0 "请求正常下高压" 1 "请求上高压" 2 "强制SBMU下高压" ;
VAL_ 2148630438 HvPwrOnCmd_SBMU08_22 0 "请求正常下高压" 1 "请求上高压" 2 "强制SBMU下高压" ;
VAL_ 2148630438 HvPwrOnCmd_SBMU09_22 0 "请求正常下高压" 1 "请求上高压" 2 "强制SBMU下高压" ;
VAL_ 2148630438 HvPwrOnCmd_SBMU10_22 0 "请求正常下高压" 1 "请求上高压" 2 "强制SBMU下高压" ;
VAL_ 2148630438 HvPwrOnCmd_SBMU11_22 0 "请求正常下高压" 1 "请求上高压" 2 "强制SBMU下高压" ;
VAL_ 2148630438 HvPwrOnCmd_SBMU12_22 0 "请求正常下高压" 1 "请求上高压" 2 "强制SBMU下高压" ;
VAL_ 2148630438 HvPwrOnCmd_SBMU13_22 0 "请求正常下高压" 1 "请求上高压" 2 "强制SBMU下高压" ;
VAL_ 2148630438 HvPwrOnCmd_SBMU14_22 0 "请求正常下高压" 1 "请求上高压" 2 "强制SBMU下高压" ;
VAL_ 2148630438 HvPwrOnCmd_SBMU15_22 0 "请求正常下高压" 1 "请求上高压" 2 "强制SBMU下高压" ;
VAL_ 2148630438 HvPwrOnCmd_SBMU16_22 0 "请求正常下高压" 1 "请求上高压" 2 "强制SBMU下高压" ;
VAL_ 2148630438 HvPwrOnCmd_SBMU17_22 0 "请求正常下高压" 1 "请求上高压" 2 "强制SBMU下高压" ;
VAL_ 2148630438 HvPwrOnCmd_SBMU18_22 0 "请求正常下高压" 1 "请求上高压" 2 "强制SBMU下高压" ;
VAL_ 2148630438 HvPwrOnCmd_SBMU19_22 0 "请求正常下高压" 1 "请求上高压" 2 "强制SBMU下高压" ;
VAL_ 2148630438 HvPwrOnCmd_SBMU20_22 0 "请求正常下高压" 1 "请求上高压" 2 "强制SBMU下高压" ;
VAL_ 2148630438 HvPwrOnCmd_SBMU21_22 0 "请求正常下高压" 1 "请求上高压" 2 "强制SBMU下高压" ;
VAL_ 2148630438 HvPwrOnCmd_SBMU22_22 0 "请求正常下高压" 1 "请求上高压" 2 "强制SBMU下高压" ;
VAL_ 2148630438 HvPwrOnCmd_SBMU23_22 0 "请求正常下高压" 1 "请求上高压" 2 "强制SBMU下高压" ;
VAL_ 2148630438 HvPwrOnCmd_SBMU24_22 0 "请求正常下高压" 1 "请求上高压" 2 "强制SBMU下高压" ;
VAL_ 2148630438 HvPwrOnCmd_SBMU25_22 0 "请求正常下高压" 1 "请求上高压" 2 "强制SBMU下高压" ;
VAL_ 2148630438 HvPwrOnCmd_SBMU26_22 0 "请求正常下高压" 1 "请求上高压" 2 "强制SBMU下高压" ;
VAL_ 2148630438 HvPwrOnCmd_SBMU27_22 0 "请求正常下高压" 1 "请求上高压" 2 "强制SBMU下高压" ;
VAL_ 2148630438 HvPwrOnCmd_SBMU28_22 0 "请求正常下高压" 1 "请求上高压" 2 "强制SBMU下高压" ;
VAL_ 2148630438 HvPwrOnCmd_SBMU29_22 0 "请求正常下高压" 1 "请求上高压" 2 "强制SBMU下高压" ;
VAL_ 2148630438 HvPwrOnCmd_SBMU30_22 0 "请求正常下高压" 1 "请求上高压" 2 "强制SBMU下高压" ;
VAL_ 2148630438 HvPwrOnCmd_SBMU31_22 0 "请求正常下高压" 1 "请求上高压" 2 "强制SBMU下高压" ;
VAL_ 2148630438 HvPwrOnCmd_SBMU32_22 0 "请求正常下高压" 1 "请求上高压" 2 "强制SBMU下高压" ;
VAL_ 2148630439 HvPwrOnCmd_SBMU01_23 0 "请求正常下高压" 1 "请求上高压" 2 "强制SBMU下高压" ;
VAL_ 2148630439 HvPwrOnCmd_SBMU02_23 0 "请求正常下高压" 1 "请求上高压" 2 "强制SBMU下高压" ;
VAL_ 2148630439 HvPwrOnCmd_SBMU03_23 0 "请求正常下高压" 1 "请求上高压" 2 "强制SBMU下高压" ;
VAL_ 2148630439 HvPwrOnCmd_SBMU04_23 0 "请求正常下高压" 1 "请求上高压" 2 "强制SBMU下高压" ;
VAL_ 2148630439 HvPwrOnCmd_SBMU05_23 0 "请求正常下高压" 1 "请求上高压" 2 "强制SBMU下高压" ;
VAL_ 2148630439 HvPwrOnCmd_SBMU06_23 0 "请求正常下高压" 1 "请求上高压" 2 "强制SBMU下高压" ;
VAL_ 2148630439 HvPwrOnCmd_SBMU07_23 0 "请求正常下高压" 1 "请求上高压" 2 "强制SBMU下高压" ;
VAL_ 2148630439 HvPwrOnCmd_SBMU08_23 0 "请求正常下高压" 1 "请求上高压" 2 "强制SBMU下高压" ;
VAL_ 2148630439 HvPwrOnCmd_SBMU09_23 0 "请求正常下高压" 1 "请求上高压" 2 "强制SBMU下高压" ;
VAL_ 2148630439 HvPwrOnCmd_SBMU10_23 0 "请求正常下高压" 1 "请求上高压" 2 "强制SBMU下高压" ;
VAL_ 2148630439 HvPwrOnCmd_SBMU11_23 0 "请求正常下高压" 1 "请求上高压" 2 "强制SBMU下高压" ;
VAL_ 2148630439 HvPwrOnCmd_SBMU12_23 0 "请求正常下高压" 1 "请求上高压" 2 "强制SBMU下高压" ;
VAL_ 2148630439 HvPwrOnCmd_SBMU13_23 0 "请求正常下高压" 1 "请求上高压" 2 "强制SBMU下高压" ;
VAL_ 2148630439 HvPwrOnCmd_SBMU14_23 0 "请求正常下高压" 1 "请求上高压" 2 "强制SBMU下高压" ;
VAL_ 2148630439 HvPwrOnCmd_SBMU15_23 0 "请求正常下高压" 1 "请求上高压" 2 "强制SBMU下高压" ;
VAL_ 2148630439 HvPwrOnCmd_SBMU16_23 0 "请求正常下高压" 1 "请求上高压" 2 "强制SBMU下高压" ;
VAL_ 2148630439 HvPwrOnCmd_SBMU17_23 0 "请求正常下高压" 1 "请求上高压" 2 "强制SBMU下高压" ;
VAL_ 2148630439 HvPwrOnCmd_SBMU18_23 0 "请求正常下高压" 1 "请求上高压" 2 "强制SBMU下高压" ;
VAL_ 2148630439 HvPwrOnCmd_SBMU19_23 0 "请求正常下高压" 1 "请求上高压" 2 "强制SBMU下高压" ;
VAL_ 2148630439 HvPwrOnCmd_SBMU20_23 0 "请求正常下高压" 1 "请求上高压" 2 "强制SBMU下高压" ;
VAL_ 2148630439 HvPwrOnCmd_SBMU21_23 0 "请求正常下高压" 1 "请求上高压" 2 "强制SBMU下高压" ;
VAL_ 2148630439 HvPwrOnCmd_SBMU22_23 0 "请求正常下高压" 1 "请求上高压" 2 "强制SBMU下高压" ;
VAL_ 2148630439 HvPwrOnCmd_SBMU23_23 0 "请求正常下高压" 1 "请求上高压" 2 "强制SBMU下高压" ;
VAL_ 2148630439 HvPwrOnCmd_SBMU24_23 0 "请求正常下高压" 1 "请求上高压" 2 "强制SBMU下高压" ;
VAL_ 2148630439 HvPwrOnCmd_SBMU25_23 0 "请求正常下高压" 1 "请求上高压" 2 "强制SBMU下高压" ;
VAL_ 2148630439 HvPwrOnCmd_SBMU26_23 0 "请求正常下高压" 1 "请求上高压" 2 "强制SBMU下高压" ;
VAL_ 2148630439 HvPwrOnCmd_SBMU27_23 0 "请求正常下高压" 1 "请求上高压" 2 "强制SBMU下高压" ;
VAL_ 2148630439 HvPwrOnCmd_SBMU28_23 0 "请求正常下高压" 1 "请求上高压" 2 "强制SBMU下高压" ;
VAL_ 2148630439 HvPwrOnCmd_SBMU29_23 0 "请求正常下高压" 1 "请求上高压" 2 "强制SBMU下高压" ;
VAL_ 2148630439 HvPwrOnCmd_SBMU30_23 0 "请求正常下高压" 1 "请求上高压" 2 "强制SBMU下高压" ;
VAL_ 2148630439 HvPwrOnCmd_SBMU31_23 0 "请求正常下高压" 1 "请求上高压" 2 "强制SBMU下高压" ;
VAL_ 2148630439 HvPwrOnCmd_SBMU32_23 0 "请求正常下高压" 1 "请求上高压" 2 "强制SBMU下高压" ;
VAL_ 2148630440 HvPwrOnCmd_SBMU01_24 0 "请求正常下高压" 1 "请求上高压" 2 "强制SBMU下高压" ;
VAL_ 2148630440 HvPwrOnCmd_SBMU02_24 0 "请求正常下高压" 1 "请求上高压" 2 "强制SBMU下高压" ;
VAL_ 2148630440 HvPwrOnCmd_SBMU03_24 0 "请求正常下高压" 1 "请求上高压" 2 "强制SBMU下高压" ;
VAL_ 2148630440 HvPwrOnCmd_SBMU04_24 0 "请求正常下高压" 1 "请求上高压" 2 "强制SBMU下高压" ;
VAL_ 2148630440 HvPwrOnCmd_SBMU05_24 0 "请求正常下高压" 1 "请求上高压" 2 "强制SBMU下高压" ;
VAL_ 2148630440 HvPwrOnCmd_SBMU06_24 0 "请求正常下高压" 1 "请求上高压" 2 "强制SBMU下高压" ;
VAL_ 2148630440 HvPwrOnCmd_SBMU07_24 0 "请求正常下高压" 1 "请求上高压" 2 "强制SBMU下高压" ;
VAL_ 2148630440 HvPwrOnCmd_SBMU08_24 0 "请求正常下高压" 1 "请求上高压" 2 "强制SBMU下高压" ;
VAL_ 2148630440 HvPwrOnCmd_SBMU09_24 0 "请求正常下高压" 1 "请求上高压" 2 "强制SBMU下高压" ;
VAL_ 2148630440 HvPwrOnCmd_SBMU10_24 0 "请求正常下高压" 1 "请求上高压" 2 "强制SBMU下高压" ;
VAL_ 2148630440 HvPwrOnCmd_SBMU11_24 0 "请求正常下高压" 1 "请求上高压" 2 "强制SBMU下高压" ;
VAL_ 2148630440 HvPwrOnCmd_SBMU12_24 0 "请求正常下高压" 1 "请求上高压" 2 "强制SBMU下高压" ;
VAL_ 2148630440 HvPwrOnCmd_SBMU13_24 0 "请求正常下高压" 1 "请求上高压" 2 "强制SBMU下高压" ;
VAL_ 2148630440 HvPwrOnCmd_SBMU14_24 0 "请求正常下高压" 1 "请求上高压" 2 "强制SBMU下高压" ;
VAL_ 2148630440 HvPwrOnCmd_SBMU15_24 0 "请求正常下高压" 1 "请求上高压" 2 "强制SBMU下高压" ;
VAL_ 2148630440 HvPwrOnCmd_SBMU16_24 0 "请求正常下高压" 1 "请求上高压" 2 "强制SBMU下高压" ;
VAL_ 2148630440 HvPwrOnCmd_SBMU17_24 0 "请求正常下高压" 1 "请求上高压" 2 "强制SBMU下高压" ;
VAL_ 2148630440 HvPwrOnCmd_SBMU18_24 0 "请求正常下高压" 1 "请求上高压" 2 "强制SBMU下高压" ;
VAL_ 2148630440 HvPwrOnCmd_SBMU19_24 0 "请求正常下高压" 1 "请求上高压" 2 "强制SBMU下高压" ;
VAL_ 2148630440 HvPwrOnCmd_SBMU20_24 0 "请求正常下高压" 1 "请求上高压" 2 "强制SBMU下高压" ;
VAL_ 2148630440 HvPwrOnCmd_SBMU21_24 0 "请求正常下高压" 1 "请求上高压" 2 "强制SBMU下高压" ;
VAL_ 2148630440 HvPwrOnCmd_SBMU22_24 0 "请求正常下高压" 1 "请求上高压" 2 "强制SBMU下高压" ;
VAL_ 2148630440 HvPwrOnCmd_SBMU23_24 0 "请求正常下高压" 1 "请求上高压" 2 "强制SBMU下高压" ;
VAL_ 2148630440 HvPwrOnCmd_SBMU24_24 0 "请求正常下高压" 1 "请求上高压" 2 "强制SBMU下高压" ;
VAL_ 2148630440 HvPwrOnCmd_SBMU25_24 0 "请求正常下高压" 1 "请求上高压" 2 "强制SBMU下高压" ;
VAL_ 2148630440 HvPwrOnCmd_SBMU26_24 0 "请求正常下高压" 1 "请求上高压" 2 "强制SBMU下高压" ;
VAL_ 2148630440 HvPwrOnCmd_SBMU27_24 0 "请求正常下高压" 1 "请求上高压" 2 "强制SBMU下高压" ;
VAL_ 2148630440 HvPwrOnCmd_SBMU28_24 0 "请求正常下高压" 1 "请求上高压" 2 "强制SBMU下高压" ;
VAL_ 2148630440 HvPwrOnCmd_SBMU29_24 0 "请求正常下高压" 1 "请求上高压" 2 "强制SBMU下高压" ;
VAL_ 2148630440 HvPwrOnCmd_SBMU30_24 0 "请求正常下高压" 1 "请求上高压" 2 "强制SBMU下高压" ;
VAL_ 2148630440 HvPwrOnCmd_SBMU31_24 0 "请求正常下高压" 1 "请求上高压" 2 "强制SBMU下高压" ;
VAL_ 2148630440 HvPwrOnCmd_SBMU32_24 0 "请求正常下高压" 1 "请求上高压" 2 "强制SBMU下高压" ;
VAL_ 2148630441 HvPwrOnCmd_SBMU01_25 0 "请求正常下高压" 1 "请求上高压" 2 "强制SBMU下高压" ;
VAL_ 2148630441 HvPwrOnCmd_SBMU02_25 0 "请求正常下高压" 1 "请求上高压" 2 "强制SBMU下高压" ;
VAL_ 2148630441 HvPwrOnCmd_SBMU03_25 0 "请求正常下高压" 1 "请求上高压" 2 "强制SBMU下高压" ;
VAL_ 2148630441 HvPwrOnCmd_SBMU04_25 0 "请求正常下高压" 1 "请求上高压" 2 "强制SBMU下高压" ;
VAL_ 2148630441 HvPwrOnCmd_SBMU05_25 0 "请求正常下高压" 1 "请求上高压" 2 "强制SBMU下高压" ;
VAL_ 2148630441 HvPwrOnCmd_SBMU06_25 0 "请求正常下高压" 1 "请求上高压" 2 "强制SBMU下高压" ;
VAL_ 2148630441 HvPwrOnCmd_SBMU07_25 0 "请求正常下高压" 1 "请求上高压" 2 "强制SBMU下高压" ;
VAL_ 2148630441 HvPwrOnCmd_SBMU08_25 0 "请求正常下高压" 1 "请求上高压" 2 "强制SBMU下高压" ;
VAL_ 2148630441 HvPwrOnCmd_SBMU09_25 0 "请求正常下高压" 1 "请求上高压" 2 "强制SBMU下高压" ;
VAL_ 2148630441 HvPwrOnCmd_SBMU10_25 0 "请求正常下高压" 1 "请求上高压" 2 "强制SBMU下高压" ;
VAL_ 2148630441 HvPwrOnCmd_SBMU11_25 0 "请求正常下高压" 1 "请求上高压" 2 "强制SBMU下高压" ;
VAL_ 2148630441 HvPwrOnCmd_SBMU12_25 0 "请求正常下高压" 1 "请求上高压" 2 "强制SBMU下高压" ;
VAL_ 2148630441 HvPwrOnCmd_SBMU13_25 0 "请求正常下高压" 1 "请求上高压" 2 "强制SBMU下高压" ;
VAL_ 2148630441 HvPwrOnCmd_SBMU14_25 0 "请求正常下高压" 1 "请求上高压" 2 "强制SBMU下高压" ;
VAL_ 2148630441 HvPwrOnCmd_SBMU15_25 0 "请求正常下高压" 1 "请求上高压" 2 "强制SBMU下高压" ;
VAL_ 2148630441 HvPwrOnCmd_SBMU16_25 0 "请求正常下高压" 1 "请求上高压" 2 "强制SBMU下高压" ;
VAL_ 2148630441 HvPwrOnCmd_SBMU17_25 0 "请求正常下高压" 1 "请求上高压" 2 "强制SBMU下高压" ;
VAL_ 2148630441 HvPwrOnCmd_SBMU18_25 0 "请求正常下高压" 1 "请求上高压" 2 "强制SBMU下高压" ;
VAL_ 2148630441 HvPwrOnCmd_SBMU19_25 0 "请求正常下高压" 1 "请求上高压" 2 "强制SBMU下高压" ;
VAL_ 2148630441 HvPwrOnCmd_SBMU20_25 0 "请求正常下高压" 1 "请求上高压" 2 "强制SBMU下高压" ;
VAL_ 2148630441 HvPwrOnCmd_SBMU21_25 0 "请求正常下高压" 1 "请求上高压" 2 "强制SBMU下高压" ;
VAL_ 2148630441 HvPwrOnCmd_SBMU22_25 0 "请求正常下高压" 1 "请求上高压" 2 "强制SBMU下高压" ;
VAL_ 2148630441 HvPwrOnCmd_SBMU23_25 0 "请求正常下高压" 1 "请求上高压" 2 "强制SBMU下高压" ;
VAL_ 2148630441 HvPwrOnCmd_SBMU24_25 0 "请求正常下高压" 1 "请求上高压" 2 "强制SBMU下高压" ;
VAL_ 2148630441 HvPwrOnCmd_SBMU25_25 0 "请求正常下高压" 1 "请求上高压" 2 "强制SBMU下高压" ;
VAL_ 2148630441 HvPwrOnCmd_SBMU26_25 0 "请求正常下高压" 1 "请求上高压" 2 "强制SBMU下高压" ;
VAL_ 2148630441 HvPwrOnCmd_SBMU27_25 0 "请求正常下高压" 1 "请求上高压" 2 "强制SBMU下高压" ;
VAL_ 2148630441 HvPwrOnCmd_SBMU28_25 0 "请求正常下高压" 1 "请求上高压" 2 "强制SBMU下高压" ;
VAL_ 2148630441 HvPwrOnCmd_SBMU29_25 0 "请求正常下高压" 1 "请求上高压" 2 "强制SBMU下高压" ;
VAL_ 2148630441 HvPwrOnCmd_SBMU30_25 0 "请求正常下高压" 1 "请求上高压" 2 "强制SBMU下高压" ;
VAL_ 2148630441 HvPwrOnCmd_SBMU31_25 0 "请求正常下高压" 1 "请求上高压" 2 "强制SBMU下高压" ;
VAL_ 2148630441 HvPwrOnCmd_SBMU32_25 0 "请求正常下高压" 1 "请求上高压" 2 "强制SBMU下高压" ;
VAL_ 2148630442 HvPwrOnCmd_SBMU01_26 0 "请求正常下高压" 1 "请求上高压" 2 "强制SBMU下高压" ;
VAL_ 2148630442 HvPwrOnCmd_SBMU02_26 0 "请求正常下高压" 1 "请求上高压" 2 "强制SBMU下高压" ;
VAL_ 2148630442 HvPwrOnCmd_SBMU03_26 0 "请求正常下高压" 1 "请求上高压" 2 "强制SBMU下高压" ;
VAL_ 2148630442 HvPwrOnCmd_SBMU04_26 0 "请求正常下高压" 1 "请求上高压" 2 "强制SBMU下高压" ;
VAL_ 2148630442 HvPwrOnCmd_SBMU05_26 0 "请求正常下高压" 1 "请求上高压" 2 "强制SBMU下高压" ;
VAL_ 2148630442 HvPwrOnCmd_SBMU06_26 0 "请求正常下高压" 1 "请求上高压" 2 "强制SBMU下高压" ;
VAL_ 2148630442 HvPwrOnCmd_SBMU07_26 0 "请求正常下高压" 1 "请求上高压" 2 "强制SBMU下高压" ;
VAL_ 2148630442 HvPwrOnCmd_SBMU08_26 0 "请求正常下高压" 1 "请求上高压" 2 "强制SBMU下高压" ;
VAL_ 2148630442 HvPwrOnCmd_SBMU09_26 0 "请求正常下高压" 1 "请求上高压" 2 "强制SBMU下高压" ;
VAL_ 2148630442 HvPwrOnCmd_SBMU10_26 0 "请求正常下高压" 1 "请求上高压" 2 "强制SBMU下高压" ;
VAL_ 2148630442 HvPwrOnCmd_SBMU11_26 0 "请求正常下高压" 1 "请求上高压" 2 "强制SBMU下高压" ;
VAL_ 2148630442 HvPwrOnCmd_SBMU12_26 0 "请求正常下高压" 1 "请求上高压" 2 "强制SBMU下高压" ;
VAL_ 2148630442 HvPwrOnCmd_SBMU13_26 0 "请求正常下高压" 1 "请求上高压" 2 "强制SBMU下高压" ;
VAL_ 2148630442 HvPwrOnCmd_SBMU14_26 0 "请求正常下高压" 1 "请求上高压" 2 "强制SBMU下高压" ;
VAL_ 2148630442 HvPwrOnCmd_SBMU15_26 0 "请求正常下高压" 1 "请求上高压" 2 "强制SBMU下高压" ;
VAL_ 2148630442 HvPwrOnCmd_SBMU16_26 0 "请求正常下高压" 1 "请求上高压" 2 "强制SBMU下高压" ;
VAL_ 2148630442 HvPwrOnCmd_SBMU17_26 0 "请求正常下高压" 1 "请求上高压" 2 "强制SBMU下高压" ;
VAL_ 2148630442 HvPwrOnCmd_SBMU18_26 0 "请求正常下高压" 1 "请求上高压" 2 "强制SBMU下高压" ;
VAL_ 2148630442 HvPwrOnCmd_SBMU19_26 0 "请求正常下高压" 1 "请求上高压" 2 "强制SBMU下高压" ;
VAL_ 2148630442 HvPwrOnCmd_SBMU20_26 0 "请求正常下高压" 1 "请求上高压" 2 "强制SBMU下高压" ;
VAL_ 2148630442 HvPwrOnCmd_SBMU21_26 0 "请求正常下高压" 1 "请求上高压" 2 "强制SBMU下高压" ;
VAL_ 2148630442 HvPwrOnCmd_SBMU22_26 0 "请求正常下高压" 1 "请求上高压" 2 "强制SBMU下高压" ;
VAL_ 2148630442 HvPwrOnCmd_SBMU23_26 0 "请求正常下高压" 1 "请求上高压" 2 "强制SBMU下高压" ;
VAL_ 2148630442 HvPwrOnCmd_SBMU24_26 0 "请求正常下高压" 1 "请求上高压" 2 "强制SBMU下高压" ;
VAL_ 2148630442 HvPwrOnCmd_SBMU25_26 0 "请求正常下高压" 1 "请求上高压" 2 "强制SBMU下高压" ;
VAL_ 2148630442 HvPwrOnCmd_SBMU26_26 0 "请求正常下高压" 1 "请求上高压" 2 "强制SBMU下高压" ;
VAL_ 2148630442 HvPwrOnCmd_SBMU27_26 0 "请求正常下高压" 1 "请求上高压" 2 "强制SBMU下高压" ;
VAL_ 2148630442 HvPwrOnCmd_SBMU28_26 0 "请求正常下高压" 1 "请求上高压" 2 "强制SBMU下高压" ;
VAL_ 2148630442 HvPwrOnCmd_SBMU29_26 0 "请求正常下高压" 1 "请求上高压" 2 "强制SBMU下高压" ;
VAL_ 2148630442 HvPwrOnCmd_SBMU30_26 0 "请求正常下高压" 1 "请求上高压" 2 "强制SBMU下高压" ;
VAL_ 2148630442 HvPwrOnCmd_SBMU31_26 0 "请求正常下高压" 1 "请求上高压" 2 "强制SBMU下高压" ;
VAL_ 2148630442 HvPwrOnCmd_SBMU32_26 0 "请求正常下高压" 1 "请求上高压" 2 "强制SBMU下高压" ;
VAL_ 2148630443 HvPwrOnCmd_SBMU01_27 0 "请求正常下高压" 1 "请求上高压" 2 "强制SBMU下高压" ;
VAL_ 2148630443 HvPwrOnCmd_SBMU02_27 0 "请求正常下高压" 1 "请求上高压" 2 "强制SBMU下高压" ;
VAL_ 2148630443 HvPwrOnCmd_SBMU03_27 0 "请求正常下高压" 1 "请求上高压" 2 "强制SBMU下高压" ;
VAL_ 2148630443 HvPwrOnCmd_SBMU04_27 0 "请求正常下高压" 1 "请求上高压" 2 "强制SBMU下高压" ;
VAL_ 2148630443 HvPwrOnCmd_SBMU05_27 0 "请求正常下高压" 1 "请求上高压" 2 "强制SBMU下高压" ;
VAL_ 2148630443 HvPwrOnCmd_SBMU06_27 0 "请求正常下高压" 1 "请求上高压" 2 "强制SBMU下高压" ;
VAL_ 2148630443 HvPwrOnCmd_SBMU07_27 0 "请求正常下高压" 1 "请求上高压" 2 "强制SBMU下高压" ;
VAL_ 2148630443 HvPwrOnCmd_SBMU08_27 0 "请求正常下高压" 1 "请求上高压" 2 "强制SBMU下高压" ;
VAL_ 2148630443 HvPwrOnCmd_SBMU09_27 0 "请求正常下高压" 1 "请求上高压" 2 "强制SBMU下高压" ;
VAL_ 2148630443 HvPwrOnCmd_SBMU10_27 0 "请求正常下高压" 1 "请求上高压" 2 "强制SBMU下高压" ;
VAL_ 2148630443 HvPwrOnCmd_SBMU11_27 0 "请求正常下高压" 1 "请求上高压" 2 "强制SBMU下高压" ;
VAL_ 2148630443 HvPwrOnCmd_SBMU12_27 0 "请求正常下高压" 1 "请求上高压" 2 "强制SBMU下高压" ;
VAL_ 2148630443 HvPwrOnCmd_SBMU13_27 0 "请求正常下高压" 1 "请求上高压" 2 "强制SBMU下高压" ;
VAL_ 2148630443 HvPwrOnCmd_SBMU14_27 0 "请求正常下高压" 1 "请求上高压" 2 "强制SBMU下高压" ;
VAL_ 2148630443 HvPwrOnCmd_SBMU15_27 0 "请求正常下高压" 1 "请求上高压" 2 "强制SBMU下高压" ;
VAL_ 2148630443 HvPwrOnCmd_SBMU16_27 0 "请求正常下高压" 1 "请求上高压" 2 "强制SBMU下高压" ;
VAL_ 2148630443 HvPwrOnCmd_SBMU17_27 0 "请求正常下高压" 1 "请求上高压" 2 "强制SBMU下高压" ;
VAL_ 2148630443 HvPwrOnCmd_SBMU18_27 0 "请求正常下高压" 1 "请求上高压" 2 "强制SBMU下高压" ;
VAL_ 2148630443 HvPwrOnCmd_SBMU19_27 0 "请求正常下高压" 1 "请求上高压" 2 "强制SBMU下高压" ;
VAL_ 2148630443 HvPwrOnCmd_SBMU20_27 0 "请求正常下高压" 1 "请求上高压" 2 "强制SBMU下高压" ;
VAL_ 2148630443 HvPwrOnCmd_SBMU21_27 0 "请求正常下高压" 1 "请求上高压" 2 "强制SBMU下高压" ;
VAL_ 2148630443 HvPwrOnCmd_SBMU22_27 0 "请求正常下高压" 1 "请求上高压" 2 "强制SBMU下高压" ;
VAL_ 2148630443 HvPwrOnCmd_SBMU23_27 0 "请求正常下高压" 1 "请求上高压" 2 "强制SBMU下高压" ;
VAL_ 2148630443 HvPwrOnCmd_SBMU24_27 0 "请求正常下高压" 1 "请求上高压" 2 "强制SBMU下高压" ;
VAL_ 2148630443 HvPwrOnCmd_SBMU25_27 0 "请求正常下高压" 1 "请求上高压" 2 "强制SBMU下高压" ;
VAL_ 2148630443 HvPwrOnCmd_SBMU26_27 0 "请求正常下高压" 1 "请求上高压" 2 "强制SBMU下高压" ;
VAL_ 2148630443 HvPwrOnCmd_SBMU27_27 0 "请求正常下高压" 1 "请求上高压" 2 "强制SBMU下高压" ;
VAL_ 2148630443 HvPwrOnCmd_SBMU28_27 0 "请求正常下高压" 1 "请求上高压" 2 "强制SBMU下高压" ;
VAL_ 2148630443 HvPwrOnCmd_SBMU29_27 0 "请求正常下高压" 1 "请求上高压" 2 "强制SBMU下高压" ;
VAL_ 2148630443 HvPwrOnCmd_SBMU30_27 0 "请求正常下高压" 1 "请求上高压" 2 "强制SBMU下高压" ;
VAL_ 2148630443 HvPwrOnCmd_SBMU31_27 0 "请求正常下高压" 1 "请求上高压" 2 "强制SBMU下高压" ;
VAL_ 2148630443 HvPwrOnCmd_SBMU32_27 0 "请求正常下高压" 1 "请求上高压" 2 "强制SBMU下高压" ;
VAL_ 2148630444 HvPwrOnCmd_SBMU01_28 0 "请求正常下高压" 1 "请求上高压" 2 "强制SBMU下高压" ;
VAL_ 2148630444 HvPwrOnCmd_SBMU02_28 0 "请求正常下高压" 1 "请求上高压" 2 "强制SBMU下高压" ;
VAL_ 2148630444 HvPwrOnCmd_SBMU03_28 0 "请求正常下高压" 1 "请求上高压" 2 "强制SBMU下高压" ;
VAL_ 2148630444 HvPwrOnCmd_SBMU04_28 0 "请求正常下高压" 1 "请求上高压" 2 "强制SBMU下高压" ;
VAL_ 2148630444 HvPwrOnCmd_SBMU05_28 0 "请求正常下高压" 1 "请求上高压" 2 "强制SBMU下高压" ;
VAL_ 2148630444 HvPwrOnCmd_SBMU06_28 0 "请求正常下高压" 1 "请求上高压" 2 "强制SBMU下高压" ;
VAL_ 2148630444 HvPwrOnCmd_SBMU07_28 0 "请求正常下高压" 1 "请求上高压" 2 "强制SBMU下高压" ;
VAL_ 2148630444 HvPwrOnCmd_SBMU08_28 0 "请求正常下高压" 1 "请求上高压" 2 "强制SBMU下高压" ;
VAL_ 2148630444 HvPwrOnCmd_SBMU09_28 0 "请求正常下高压" 1 "请求上高压" 2 "强制SBMU下高压" ;
VAL_ 2148630444 HvPwrOnCmd_SBMU10_28 0 "请求正常下高压" 1 "请求上高压" 2 "强制SBMU下高压" ;
VAL_ 2148630444 HvPwrOnCmd_SBMU11_28 0 "请求正常下高压" 1 "请求上高压" 2 "强制SBMU下高压" ;
VAL_ 2148630444 HvPwrOnCmd_SBMU12_28 0 "请求正常下高压" 1 "请求上高压" 2 "强制SBMU下高压" ;
VAL_ 2148630444 HvPwrOnCmd_SBMU13_28 0 "请求正常下高压" 1 "请求上高压" 2 "强制SBMU下高压" ;
VAL_ 2148630444 HvPwrOnCmd_SBMU14_28 0 "请求正常下高压" 1 "请求上高压" 2 "强制SBMU下高压" ;
VAL_ 2148630444 HvPwrOnCmd_SBMU15_28 0 "请求正常下高压" 1 "请求上高压" 2 "强制SBMU下高压" ;
VAL_ 2148630444 HvPwrOnCmd_SBMU16_28 0 "请求正常下高压" 1 "请求上高压" 2 "强制SBMU下高压" ;
VAL_ 2148630444 HvPwrOnCmd_SBMU17_28 0 "请求正常下高压" 1 "请求上高压" 2 "强制SBMU下高压" ;
VAL_ 2148630444 HvPwrOnCmd_SBMU18_28 0 "请求正常下高压" 1 "请求上高压" 2 "强制SBMU下高压" ;
VAL_ 2148630444 HvPwrOnCmd_SBMU19_28 0 "请求正常下高压" 1 "请求上高压" 2 "强制SBMU下高压" ;
VAL_ 2148630444 HvPwrOnCmd_SBMU20_28 0 "请求正常下高压" 1 "请求上高压" 2 "强制SBMU下高压" ;
VAL_ 2148630444 HvPwrOnCmd_SBMU21_28 0 "请求正常下高压" 1 "请求上高压" 2 "强制SBMU下高压" ;
VAL_ 2148630444 HvPwrOnCmd_SBMU22_28 0 "请求正常下高压" 1 "请求上高压" 2 "强制SBMU下高压" ;
VAL_ 2148630444 HvPwrOnCmd_SBMU23_28 0 "请求正常下高压" 1 "请求上高压" 2 "强制SBMU下高压" ;
VAL_ 2148630444 HvPwrOnCmd_SBMU24_28 0 "请求正常下高压" 1 "请求上高压" 2 "强制SBMU下高压" ;
VAL_ 2148630444 HvPwrOnCmd_SBMU25_28 0 "请求正常下高压" 1 "请求上高压" 2 "强制SBMU下高压" ;
VAL_ 2148630444 HvPwrOnCmd_SBMU26_28 0 "请求正常下高压" 1 "请求上高压" 2 "强制SBMU下高压" ;
VAL_ 2148630444 HvPwrOnCmd_SBMU27_28 0 "请求正常下高压" 1 "请求上高压" 2 "强制SBMU下高压" ;
VAL_ 2148630444 HvPwrOnCmd_SBMU28_28 0 "请求正常下高压" 1 "请求上高压" 2 "强制SBMU下高压" ;
VAL_ 2148630444 HvPwrOnCmd_SBMU29_28 0 "请求正常下高压" 1 "请求上高压" 2 "强制SBMU下高压" ;
VAL_ 2148630444 HvPwrOnCmd_SBMU30_28 0 "请求正常下高压" 1 "请求上高压" 2 "强制SBMU下高压" ;
VAL_ 2148630444 HvPwrOnCmd_SBMU31_28 0 "请求正常下高压" 1 "请求上高压" 2 "强制SBMU下高压" ;
VAL_ 2148630444 HvPwrOnCmd_SBMU32_28 0 "请求正常下高压" 1 "请求上高压" 2 "强制SBMU下高压" ;
VAL_ 2148630445 HvPwrOnCmd_SBMU01_29 0 "请求正常下高压" 1 "请求上高压" 2 "强制SBMU下高压" ;
VAL_ 2148630445 HvPwrOnCmd_SBMU02_29 0 "请求正常下高压" 1 "请求上高压" 2 "强制SBMU下高压" ;
VAL_ 2148630445 HvPwrOnCmd_SBMU03_29 0 "请求正常下高压" 1 "请求上高压" 2 "强制SBMU下高压" ;
VAL_ 2148630445 HvPwrOnCmd_SBMU04_29 0 "请求正常下高压" 1 "请求上高压" 2 "强制SBMU下高压" ;
VAL_ 2148630445 HvPwrOnCmd_SBMU05_29 0 "请求正常下高压" 1 "请求上高压" 2 "强制SBMU下高压" ;
VAL_ 2148630445 HvPwrOnCmd_SBMU06_29 0 "请求正常下高压" 1 "请求上高压" 2 "强制SBMU下高压" ;
VAL_ 2148630445 HvPwrOnCmd_SBMU07_29 0 "请求正常下高压" 1 "请求上高压" 2 "强制SBMU下高压" ;
VAL_ 2148630445 HvPwrOnCmd_SBMU08_29 0 "请求正常下高压" 1 "请求上高压" 2 "强制SBMU下高压" ;
VAL_ 2148630445 HvPwrOnCmd_SBMU09_29 0 "请求正常下高压" 1 "请求上高压" 2 "强制SBMU下高压" ;
VAL_ 2148630445 HvPwrOnCmd_SBMU10_29 0 "请求正常下高压" 1 "请求上高压" 2 "强制SBMU下高压" ;
VAL_ 2148630445 HvPwrOnCmd_SBMU11_29 0 "请求正常下高压" 1 "请求上高压" 2 "强制SBMU下高压" ;
VAL_ 2148630445 HvPwrOnCmd_SBMU12_29 0 "请求正常下高压" 1 "请求上高压" 2 "强制SBMU下高压" ;
VAL_ 2148630445 HvPwrOnCmd_SBMU13_29 0 "请求正常下高压" 1 "请求上高压" 2 "强制SBMU下高压" ;
VAL_ 2148630445 HvPwrOnCmd_SBMU14_29 0 "请求正常下高压" 1 "请求上高压" 2 "强制SBMU下高压" ;
VAL_ 2148630445 HvPwrOnCmd_SBMU15_29 0 "请求正常下高压" 1 "请求上高压" 2 "强制SBMU下高压" ;
VAL_ 2148630445 HvPwrOnCmd_SBMU16_29 0 "请求正常下高压" 1 "请求上高压" 2 "强制SBMU下高压" ;
VAL_ 2148630445 HvPwrOnCmd_SBMU17_29 0 "请求正常下高压" 1 "请求上高压" 2 "强制SBMU下高压" ;
VAL_ 2148630445 HvPwrOnCmd_SBMU18_29 0 "请求正常下高压" 1 "请求上高压" 2 "强制SBMU下高压" ;
VAL_ 2148630445 HvPwrOnCmd_SBMU19_29 0 "请求正常下高压" 1 "请求上高压" 2 "强制SBMU下高压" ;
VAL_ 2148630445 HvPwrOnCmd_SBMU20_29 0 "请求正常下高压" 1 "请求上高压" 2 "强制SBMU下高压" ;
VAL_ 2148630445 HvPwrOnCmd_SBMU21_29 0 "请求正常下高压" 1 "请求上高压" 2 "强制SBMU下高压" ;
VAL_ 2148630445 HvPwrOnCmd_SBMU22_29 0 "请求正常下高压" 1 "请求上高压" 2 "强制SBMU下高压" ;
VAL_ 2148630445 HvPwrOnCmd_SBMU23_29 0 "请求正常下高压" 1 "请求上高压" 2 "强制SBMU下高压" ;
VAL_ 2148630445 HvPwrOnCmd_SBMU24_29 0 "请求正常下高压" 1 "请求上高压" 2 "强制SBMU下高压" ;
VAL_ 2148630445 HvPwrOnCmd_SBMU25_29 0 "请求正常下高压" 1 "请求上高压" 2 "强制SBMU下高压" ;
VAL_ 2148630445 HvPwrOnCmd_SBMU26_29 0 "请求正常下高压" 1 "请求上高压" 2 "强制SBMU下高压" ;
VAL_ 2148630445 HvPwrOnCmd_SBMU27_29 0 "请求正常下高压" 1 "请求上高压" 2 "强制SBMU下高压" ;
VAL_ 2148630445 HvPwrOnCmd_SBMU28_29 0 "请求正常下高压" 1 "请求上高压" 2 "强制SBMU下高压" ;
VAL_ 2148630445 HvPwrOnCmd_SBMU29_29 0 "请求正常下高压" 1 "请求上高压" 2 "强制SBMU下高压" ;
VAL_ 2148630445 HvPwrOnCmd_SBMU30_29 0 "请求正常下高压" 1 "请求上高压" 2 "强制SBMU下高压" ;
VAL_ 2148630445 HvPwrOnCmd_SBMU31_29 0 "请求正常下高压" 1 "请求上高压" 2 "强制SBMU下高压" ;
VAL_ 2148630445 HvPwrOnCmd_SBMU32_29 0 "请求正常下高压" 1 "请求上高压" 2 "强制SBMU下高压" ;
VAL_ 2148630446 HvPwrOnCmd_SBMU01_30 0 "请求正常下高压" 1 "请求上高压" 2 "强制SBMU下高压" ;
VAL_ 2148630446 HvPwrOnCmd_SBMU02_30 0 "请求正常下高压" 1 "请求上高压" 2 "强制SBMU下高压" ;
VAL_ 2148630446 HvPwrOnCmd_SBMU03_30 0 "请求正常下高压" 1 "请求上高压" 2 "强制SBMU下高压" ;
VAL_ 2148630446 HvPwrOnCmd_SBMU04_30 0 "请求正常下高压" 1 "请求上高压" 2 "强制SBMU下高压" ;
VAL_ 2148630446 HvPwrOnCmd_SBMU05_30 0 "请求正常下高压" 1 "请求上高压" 2 "强制SBMU下高压" ;
VAL_ 2148630446 HvPwrOnCmd_SBMU06_30 0 "请求正常下高压" 1 "请求上高压" 2 "强制SBMU下高压" ;
VAL_ 2148630446 HvPwrOnCmd_SBMU07_30 0 "请求正常下高压" 1 "请求上高压" 2 "强制SBMU下高压" ;
VAL_ 2148630446 HvPwrOnCmd_SBMU08_30 0 "请求正常下高压" 1 "请求上高压" 2 "强制SBMU下高压" ;
VAL_ 2148630446 HvPwrOnCmd_SBMU09_30 0 "请求正常下高压" 1 "请求上高压" 2 "强制SBMU下高压" ;
VAL_ 2148630446 HvPwrOnCmd_SBMU10_30 0 "请求正常下高压" 1 "请求上高压" 2 "强制SBMU下高压" ;
VAL_ 2148630446 HvPwrOnCmd_SBMU11_30 0 "请求正常下高压" 1 "请求上高压" 2 "强制SBMU下高压" ;
VAL_ 2148630446 HvPwrOnCmd_SBMU12_30 0 "请求正常下高压" 1 "请求上高压" 2 "强制SBMU下高压" ;
VAL_ 2148630446 HvPwrOnCmd_SBMU13_30 0 "请求正常下高压" 1 "请求上高压" 2 "强制SBMU下高压" ;
VAL_ 2148630446 HvPwrOnCmd_SBMU14_30 0 "请求正常下高压" 1 "请求上高压" 2 "强制SBMU下高压" ;
VAL_ 2148630446 HvPwrOnCmd_SBMU15_30 0 "请求正常下高压" 1 "请求上高压" 2 "强制SBMU下高压" ;
VAL_ 2148630446 HvPwrOnCmd_SBMU16_30 0 "请求正常下高压" 1 "请求上高压" 2 "强制SBMU下高压" ;
VAL_ 2148630446 HvPwrOnCmd_SBMU17_30 0 "请求正常下高压" 1 "请求上高压" 2 "强制SBMU下高压" ;
VAL_ 2148630446 HvPwrOnCmd_SBMU18_30 0 "请求正常下高压" 1 "请求上高压" 2 "强制SBMU下高压" ;
VAL_ 2148630446 HvPwrOnCmd_SBMU19_30 0 "请求正常下高压" 1 "请求上高压" 2 "强制SBMU下高压" ;
VAL_ 2148630446 HvPwrOnCmd_SBMU20_30 0 "请求正常下高压" 1 "请求上高压" 2 "强制SBMU下高压" ;
VAL_ 2148630446 HvPwrOnCmd_SBMU21_30 0 "请求正常下高压" 1 "请求上高压" 2 "强制SBMU下高压" ;
VAL_ 2148630446 HvPwrOnCmd_SBMU22_30 0 "请求正常下高压" 1 "请求上高压" 2 "强制SBMU下高压" ;
VAL_ 2148630446 HvPwrOnCmd_SBMU23_30 0 "请求正常下高压" 1 "请求上高压" 2 "强制SBMU下高压" ;
VAL_ 2148630446 HvPwrOnCmd_SBMU24_30 0 "请求正常下高压" 1 "请求上高压" 2 "强制SBMU下高压" ;
VAL_ 2148630446 HvPwrOnCmd_SBMU25_30 0 "请求正常下高压" 1 "请求上高压" 2 "强制SBMU下高压" ;
VAL_ 2148630446 HvPwrOnCmd_SBMU26_30 0 "请求正常下高压" 1 "请求上高压" 2 "强制SBMU下高压" ;
VAL_ 2148630446 HvPwrOnCmd_SBMU27_30 0 "请求正常下高压" 1 "请求上高压" 2 "强制SBMU下高压" ;
VAL_ 2148630446 HvPwrOnCmd_SBMU28_30 0 "请求正常下高压" 1 "请求上高压" 2 "强制SBMU下高压" ;
VAL_ 2148630446 HvPwrOnCmd_SBMU29_30 0 "请求正常下高压" 1 "请求上高压" 2 "强制SBMU下高压" ;
VAL_ 2148630446 HvPwrOnCmd_SBMU30_30 0 "请求正常下高压" 1 "请求上高压" 2 "强制SBMU下高压" ;
VAL_ 2148630446 HvPwrOnCmd_SBMU31_30 0 "请求正常下高压" 1 "请求上高压" 2 "强制SBMU下高压" ;
VAL_ 2148630446 HvPwrOnCmd_SBMU32_30 0 "请求正常下高压" 1 "请求上高压" 2 "强制SBMU下高压" ;
VAL_ 2148630447 HvPwrOnCmd_SBMU01_31 0 "请求正常下高压" 1 "请求上高压" 2 "强制SBMU下高压" ;
VAL_ 2148630447 HvPwrOnCmd_SBMU02_31 0 "请求正常下高压" 1 "请求上高压" 2 "强制SBMU下高压" ;
VAL_ 2148630447 HvPwrOnCmd_SBMU03_31 0 "请求正常下高压" 1 "请求上高压" 2 "强制SBMU下高压" ;
VAL_ 2148630447 HvPwrOnCmd_SBMU04_31 0 "请求正常下高压" 1 "请求上高压" 2 "强制SBMU下高压" ;
VAL_ 2148630447 HvPwrOnCmd_SBMU05_31 0 "请求正常下高压" 1 "请求上高压" 2 "强制SBMU下高压" ;
VAL_ 2148630447 HvPwrOnCmd_SBMU06_31 0 "请求正常下高压" 1 "请求上高压" 2 "强制SBMU下高压" ;
VAL_ 2148630447 HvPwrOnCmd_SBMU07_31 0 "请求正常下高压" 1 "请求上高压" 2 "强制SBMU下高压" ;
VAL_ 2148630447 HvPwrOnCmd_SBMU08_31 0 "请求正常下高压" 1 "请求上高压" 2 "强制SBMU下高压" ;
VAL_ 2148630447 HvPwrOnCmd_SBMU09_31 0 "请求正常下高压" 1 "请求上高压" 2 "强制SBMU下高压" ;
VAL_ 2148630447 HvPwrOnCmd_SBMU10_31 0 "请求正常下高压" 1 "请求上高压" 2 "强制SBMU下高压" ;
VAL_ 2148630447 HvPwrOnCmd_SBMU11_31 0 "请求正常下高压" 1 "请求上高压" 2 "强制SBMU下高压" ;
VAL_ 2148630447 HvPwrOnCmd_SBMU12_31 0 "请求正常下高压" 1 "请求上高压" 2 "强制SBMU下高压" ;
VAL_ 2148630447 HvPwrOnCmd_SBMU13_31 0 "请求正常下高压" 1 "请求上高压" 2 "强制SBMU下高压" ;
VAL_ 2148630447 HvPwrOnCmd_SBMU14_31 0 "请求正常下高压" 1 "请求上高压" 2 "强制SBMU下高压" ;
VAL_ 2148630447 HvPwrOnCmd_SBMU15_31 0 "请求正常下高压" 1 "请求上高压" 2 "强制SBMU下高压" ;
VAL_ 2148630447 HvPwrOnCmd_SBMU16_31 0 "请求正常下高压" 1 "请求上高压" 2 "强制SBMU下高压" ;
VAL_ 2148630447 HvPwrOnCmd_SBMU17_31 0 "请求正常下高压" 1 "请求上高压" 2 "强制SBMU下高压" ;
VAL_ 2148630447 HvPwrOnCmd_SBMU18_31 0 "请求正常下高压" 1 "请求上高压" 2 "强制SBMU下高压" ;
VAL_ 2148630447 HvPwrOnCmd_SBMU19_31 0 "请求正常下高压" 1 "请求上高压" 2 "强制SBMU下高压" ;
VAL_ 2148630447 HvPwrOnCmd_SBMU20_31 0 "请求正常下高压" 1 "请求上高压" 2 "强制SBMU下高压" ;
VAL_ 2148630447 HvPwrOnCmd_SBMU21_31 0 "请求正常下高压" 1 "请求上高压" 2 "强制SBMU下高压" ;
VAL_ 2148630447 HvPwrOnCmd_SBMU22_31 0 "请求正常下高压" 1 "请求上高压" 2 "强制SBMU下高压" ;
VAL_ 2148630447 HvPwrOnCmd_SBMU23_31 0 "请求正常下高压" 1 "请求上高压" 2 "强制SBMU下高压" ;
VAL_ 2148630447 HvPwrOnCmd_SBMU24_31 0 "请求正常下高压" 1 "请求上高压" 2 "强制SBMU下高压" ;
VAL_ 2148630447 HvPwrOnCmd_SBMU25_31 0 "请求正常下高压" 1 "请求上高压" 2 "强制SBMU下高压" ;
VAL_ 2148630447 HvPwrOnCmd_SBMU26_31 0 "请求正常下高压" 1 "请求上高压" 2 "强制SBMU下高压" ;
VAL_ 2148630447 HvPwrOnCmd_SBMU27_31 0 "请求正常下高压" 1 "请求上高压" 2 "强制SBMU下高压" ;
VAL_ 2148630447 HvPwrOnCmd_SBMU28_31 0 "请求正常下高压" 1 "请求上高压" 2 "强制SBMU下高压" ;
VAL_ 2148630447 HvPwrOnCmd_SBMU29_31 0 "请求正常下高压" 1 "请求上高压" 2 "强制SBMU下高压" ;
VAL_ 2148630447 HvPwrOnCmd_SBMU30_31 0 "请求正常下高压" 1 "请求上高压" 2 "强制SBMU下高压" ;
VAL_ 2148630447 HvPwrOnCmd_SBMU31_31 0 "请求正常下高压" 1 "请求上高压" 2 "强制SBMU下高压" ;
VAL_ 2148630447 HvPwrOnCmd_SBMU32_31 0 "请求正常下高压" 1 "请求上高压" 2 "强制SBMU下高压" ;
VAL_ 2148695953 M2S_CMD2_PowerDown_01 0 "Invalid" 1 "Power down normally" 2 "Force to power down" 3 "Reserved" ;
VAL_ 2148695953 M2S_CMD2_FanCtrl_01 0 "Fan Off" 1 "Fan On" ;
VAL_ 2148695953 M2S_CMD2_Data3_01 250 "报换故障清除" 255 "所有故障清除指令" ;
VAL_ 2148695953 M2S_CMD2_FullChgFlgFromMBMU_01 0 "未满充修正" 21 "满充修正" ;
VAL_ 2148695954 M2S_CMD2_PowerDown_02 0 "Invalid" 1 "Power down normally" 2 "Force to power down" 3 "Reserved" ;
VAL_ 2148695954 M2S_CMD2_FanCtrl_02 0 "Fan Off" 1 "Fan On" ;
VAL_ 2148695954 M2S_CMD2_Data3_02 250 "报换故障清除" 255 "所有故障清除指令" ;
VAL_ 2148695954 M2S_CMD2_FullChgFlgFromMBMU_02 0 "未满充修正" 21 "满充修正" ;
VAL_ 2148695955 M2S_CMD2_PowerDown_03 0 "Invalid" 1 "Power down normally" 2 "Force to power down" 3 "Reserved" ;
VAL_ 2148695955 M2S_CMD2_FanCtrl_03 0 "Fan Off" 1 "Fan On" ;
VAL_ 2148695955 M2S_CMD2_Data3_03 250 "报换故障清除" 255 "所有故障清除指令" ;
VAL_ 2148695955 M2S_CMD2_FullChgFlgFromMBMU_03 0 "未满充修正" 21 "满充修正" ;
VAL_ 2148695956 M2S_CMD2_PowerDown_04 0 "Invalid" 1 "Power down normally" 2 "Force to power down" 3 "Reserved" ;
VAL_ 2148695956 M2S_CMD2_FanCtrl_04 0 "Fan Off" 1 "Fan On" ;
VAL_ 2148695956 M2S_CMD2_Data3_04 250 "报换故障清除" 255 "所有故障清除指令" ;
VAL_ 2148695956 M2S_CMD2_FullChgFlgFromMBMU_04 0 "未满充修正" 21 "满充修正" ;
VAL_ 2148695957 M2S_CMD2_PowerDown_05 0 "Invalid" 1 "Power down normally" 2 "Force to power down" 3 "Reserved" ;
VAL_ 2148695957 M2S_CMD2_FanCtrl_05 0 "Fan Off" 1 "Fan On" ;
VAL_ 2148695957 M2S_CMD2_Data3_05 250 "报换故障清除" 255 "所有故障清除指令" ;
VAL_ 2148695957 M2S_CMD2_FullChgFlgFromMBMU_05 0 "未满充修正" 21 "满充修正" ;
VAL_ 2148695958 M2S_CMD2_PowerDown_06 0 "Invalid" 1 "Power down normally" 2 "Force to power down" 3 "Reserved" ;
VAL_ 2148695958 M2S_CMD2_FanCtrl_06 0 "Fan Off" 1 "Fan On" ;
VAL_ 2148695958 M2S_CMD2_Data3_06 250 "报换故障清除" 255 "所有故障清除指令" ;
VAL_ 2148695958 M2S_CMD2_FullChgFlgFromMBMU_06 0 "未满充修正" 21 "满充修正" ;
VAL_ 2148695959 M2S_CMD2_PowerDown_07 0 "Invalid" 1 "Power down normally" 2 "Force to power down" 3 "Reserved" ;
VAL_ 2148695959 M2S_CMD2_FanCtrl_07 0 "Fan Off" 1 "Fan On" ;
VAL_ 2148695959 M2S_CMD2_Data3_07 250 "报换故障清除" 255 "所有故障清除指令" ;
VAL_ 2148695959 M2S_CMD2_FullChgFlgFromMBMU_07 0 "未满充修正" 21 "满充修正" ;
VAL_ 2148695960 M2S_CMD2_PowerDown_08 0 "Invalid" 1 "Power down normally" 2 "Force to power down" 3 "Reserved" ;
VAL_ 2148695960 M2S_CMD2_FanCtrl_08 0 "Fan Off" 1 "Fan On" ;
VAL_ 2148695960 M2S_CMD2_Data3_08 250 "报换故障清除" 255 "所有故障清除指令" ;
VAL_ 2148695960 M2S_CMD2_FullChgFlgFromMBMU_08 0 "未满充修正" 21 "满充修正" ;
VAL_ 2148695961 M2S_CMD2_PowerDown_09 0 "Invalid" 1 "Power down normally" 2 "Force to power down" 3 "Reserved" ;
VAL_ 2148695961 M2S_CMD2_FanCtrl_09 0 "Fan Off" 1 "Fan On" ;
VAL_ 2148695961 M2S_CMD2_Data3_09 250 "报换故障清除" 255 "所有故障清除指令" ;
VAL_ 2148695961 M2S_CMD2_FullChgFlgFromMBMU_09 0 "未满充修正" 21 "满充修正" ;
VAL_ 2148695962 M2S_CMD2_PowerDown_10 0 "Invalid" 1 "Power down normally" 2 "Force to power down" 3 "Reserved" ;
VAL_ 2148695962 M2S_CMD2_FanCtrl_10 0 "Fan Off" 1 "Fan On" ;
VAL_ 2148695962 M2S_CMD2_Data3_10 250 "报换故障清除" 255 "所有故障清除指令" ;
VAL_ 2148695962 M2S_CMD2_FullChgFlgFromMBMU_10 0 "未满充修正" 21 "满充修正" ;
VAL_ 2148695963 M2S_CMD2_PowerDown_11 0 "Invalid" 1 "Power down normally" 2 "Force to power down" 3 "Reserved" ;
VAL_ 2148695963 M2S_CMD2_FanCtrl_11 0 "Fan Off" 1 "Fan On" ;
VAL_ 2148695963 M2S_CMD2_Data3_11 250 "报换故障清除" 255 "所有故障清除指令" ;
VAL_ 2148695963 M2S_CMD2_FullChgFlgFromMBMU_11 0 "未满充修正" 21 "满充修正" ;
VAL_ 2148695964 M2S_CMD2_PowerDown_12 0 "Invalid" 1 "Power down normally" 2 "Force to power down" 3 "Reserved" ;
VAL_ 2148695964 M2S_CMD2_FanCtrl_12 0 "Fan Off" 1 "Fan On" ;
VAL_ 2148695964 M2S_CMD2_Data3_12 250 "报换故障清除" 255 "所有故障清除指令" ;
VAL_ 2148695964 M2S_CMD2_FullChgFlgFromMBMU_12 0 "未满充修正" 21 "满充修正" ;
VAL_ 2148695965 M2S_CMD2_PowerDown_13 0 "Invalid" 1 "Power down normally" 2 "Force to power down" 3 "Reserved" ;
VAL_ 2148695965 M2S_CMD2_FanCtrl_13 0 "Fan Off" 1 "Fan On" ;
VAL_ 2148695965 M2S_CMD2_Data3_13 250 "报换故障清除" 255 "所有故障清除指令" ;
VAL_ 2148695965 M2S_CMD2_FullChgFlgFromMBMU_13 0 "未满充修正" 21 "满充修正" ;
VAL_ 2148695966 M2S_CMD2_PowerDown_14 0 "Invalid" 1 "Power down normally" 2 "Force to power down" 3 "Reserved" ;
VAL_ 2148695966 M2S_CMD2_FanCtrl_14 0 "Fan Off" 1 "Fan On" ;
VAL_ 2148695966 M2S_CMD2_Data3_14 250 "报换故障清除" 255 "所有故障清除指令" ;
VAL_ 2148695966 M2S_CMD2_FullChgFlgFromMBMU_14 0 "未满充修正" 21 "满充修正" ;
VAL_ 2148695967 M2S_CMD2_PowerDown_15 0 "Invalid" 1 "Power down normally" 2 "Force to power down" 3 "Reserved" ;
VAL_ 2148695967 M2S_CMD2_FanCtrl_15 0 "Fan Off" 1 "Fan On" ;
VAL_ 2148695967 M2S_CMD2_Data3_15 250 "报换故障清除" 255 "所有故障清除指令" ;
VAL_ 2148695967 M2S_CMD2_FullChgFlgFromMBMU_15 0 "未满充修正" 21 "满充修正" ;
VAL_ 2148695968 M2S_CMD2_PowerDown_16 0 "Invalid" 1 "Power down normally" 2 "Force to power down" 3 "Reserved" ;
VAL_ 2148695968 M2S_CMD2_FanCtrl_16 0 "Fan Off" 1 "Fan On" ;
VAL_ 2148695968 M2S_CMD2_Data3_16 250 "报换故障清除" 255 "所有故障清除指令" ;
VAL_ 2148695968 M2S_CMD2_FullChgFlgFromMBMU_16 0 "未满充修正" 21 "满充修正" ;
VAL_ 2148695969 M2S_CMD2_PowerDown_17 0 "Invalid" 1 "Power down normally" 2 "Force to power down" 3 "Reserved" ;
VAL_ 2148695969 M2S_CMD2_FanCtrl_17 0 "Fan Off" 1 "Fan On" ;
VAL_ 2148695969 M2S_CMD2_Data3_17 250 "报换故障清除" 255 "所有故障清除指令" ;
VAL_ 2148695969 M2S_CMD2_FullChgFlgFromMBMU_17 0 "未满充修正" 21 "满充修正" ;
VAL_ 2148695970 M2S_CMD2_PowerDown_18 0 "Invalid" 1 "Power down normally" 2 "Force to power down" 3 "Reserved" ;
VAL_ 2148695970 M2S_CMD2_FanCtrl_18 0 "Fan Off" 1 "Fan On" ;
VAL_ 2148695970 M2S_CMD2_Data3_18 250 "报换故障清除" 255 "所有故障清除指令" ;
VAL_ 2148695970 M2S_CMD2_FullChgFlgFromMBMU_18 0 "未满充修正" 21 "满充修正" ;
VAL_ 2148695971 M2S_CMD2_PowerDown_19 0 "Invalid" 1 "Power down normally" 2 "Force to power down" 3 "Reserved" ;
VAL_ 2148695971 M2S_CMD2_FanCtrl_19 0 "Fan Off" 1 "Fan On" ;
VAL_ 2148695971 M2S_CMD2_Data3_19 250 "报换故障清除" 255 "所有故障清除指令" ;
VAL_ 2148695971 M2S_CMD2_FullChgFlgFromMBMU_19 0 "未满充修正" 21 "满充修正" ;
VAL_ 2148695972 M2S_CMD2_PowerDown_20 0 "Invalid" 1 "Power down normally" 2 "Force to power down" 3 "Reserved" ;
VAL_ 2148695972 M2S_CMD2_FanCtrl_20 0 "Fan Off" 1 "Fan On" ;
VAL_ 2148695972 M2S_CMD2_Data3_20 250 "报换故障清除" 255 "所有故障清除指令" ;
VAL_ 2148695972 M2S_CMD2_FullChgFlgFromMBMU_20 0 "未满充修正" 21 "满充修正" ;
VAL_ 2148695973 M2S_CMD2_PowerDown_21 0 "Invalid" 1 "Power down normally" 2 "Force to power down" 3 "Reserved" ;
VAL_ 2148695973 M2S_CMD2_FanCtrl_21 0 "Fan Off" 1 "Fan On" ;
VAL_ 2148695973 M2S_CMD2_Data3_21 250 "报换故障清除" 255 "所有故障清除指令" ;
VAL_ 2148695973 M2S_CMD2_FullChgFlgFromMBMU_21 0 "未满充修正" 21 "满充修正" ;
VAL_ 2148695974 M2S_CMD2_PowerDown_22 0 "Invalid" 1 "Power down normally" 2 "Force to power down" 3 "Reserved" ;
VAL_ 2148695974 M2S_CMD2_FanCtrl_22 0 "Fan Off" 1 "Fan On" ;
VAL_ 2148695974 M2S_CMD2_Data3_22 250 "报换故障清除" 255 "所有故障清除指令" ;
VAL_ 2148695974 M2S_CMD2_FullChgFlgFromMBMU_22 0 "未满充修正" 21 "满充修正" ;
VAL_ 2148695975 M2S_CMD2_PowerDown_23 0 "Invalid" 1 "Power down normally" 2 "Force to power down" 3 "Reserved" ;
VAL_ 2148695975 M2S_CMD2_FanCtrl_23 0 "Fan Off" 1 "Fan On" ;
VAL_ 2148695975 M2S_CMD2_Data3_23 250 "报换故障清除" 255 "所有故障清除指令" ;
VAL_ 2148695975 M2S_CMD2_FullChgFlgFromMBMU_23 0 "未满充修正" 21 "满充修正" ;
VAL_ 2148695976 M2S_CMD2_PowerDown_24 0 "Invalid" 1 "Power down normally" 2 "Force to power down" 3 "Reserved" ;
VAL_ 2148695976 M2S_CMD2_FanCtrl_24 0 "Fan Off" 1 "Fan On" ;
VAL_ 2148695976 M2S_CMD2_Data3_24 250 "报换故障清除" 255 "所有故障清除指令" ;
VAL_ 2148695976 M2S_CMD2_FullChgFlgFromMBMU_24 0 "未满充修正" 21 "满充修正" ;
VAL_ 2148695977 M2S_CMD2_PowerDown_25 0 "Invalid" 1 "Power down normally" 2 "Force to power down" 3 "Reserved" ;
VAL_ 2148695977 M2S_CMD2_FanCtrl_25 0 "Fan Off" 1 "Fan On" ;
VAL_ 2148695977 M2S_CMD2_Data3_25 250 "报换故障清除" 255 "所有故障清除指令" ;
VAL_ 2148695977 M2S_CMD2_FullChgFlgFromMBMU_25 0 "未满充修正" 21 "满充修正" ;
VAL_ 2148695978 M2S_CMD2_PowerDown_26 0 "Invalid" 1 "Power down normally" 2 "Force to power down" 3 "Reserved" ;
VAL_ 2148695978 M2S_CMD2_FanCtrl_26 0 "Fan Off" 1 "Fan On" ;
VAL_ 2148695978 M2S_CMD2_Data3_26 250 "报换故障清除" 255 "所有故障清除指令" ;
VAL_ 2148695978 M2S_CMD2_FullChgFlgFromMBMU_26 0 "未满充修正" 21 "满充修正" ;
VAL_ 2148695979 M2S_CMD2_PowerDown_27 0 "Invalid" 1 "Power down normally" 2 "Force to power down" 3 "Reserved" ;
VAL_ 2148695979 M2S_CMD2_FanCtrl_27 0 "Fan Off" 1 "Fan On" ;
VAL_ 2148695979 M2S_CMD2_Data3_27 250 "报换故障清除" 255 "所有故障清除指令" ;
VAL_ 2148695979 M2S_CMD2_FullChgFlgFromMBMU_27 0 "未满充修正" 21 "满充修正" ;
VAL_ 2148695980 M2S_CMD2_PowerDown_28 0 "Invalid" 1 "Power down normally" 2 "Force to power down" 3 "Reserved" ;
VAL_ 2148695980 M2S_CMD2_FanCtrl_28 0 "Fan Off" 1 "Fan On" ;
VAL_ 2148695980 M2S_CMD2_Data3_28 250 "报换故障清除" 255 "所有故障清除指令" ;
VAL_ 2148695980 M2S_CMD2_FullChgFlgFromMBMU_28 0 "未满充修正" 21 "满充修正" ;
VAL_ 2148695981 M2S_CMD2_PowerDown_29 0 "Invalid" 1 "Power down normally" 2 "Force to power down" 3 "Reserved" ;
VAL_ 2148695981 M2S_CMD2_FanCtrl_29 0 "Fan Off" 1 "Fan On" ;
VAL_ 2148695981 M2S_CMD2_Data3_29 250 "报换故障清除" 255 "所有故障清除指令" ;
VAL_ 2148695981 M2S_CMD2_FullChgFlgFromMBMU_29 0 "未满充修正" 21 "满充修正" ;
VAL_ 2148695982 M2S_CMD2_PowerDown_30 0 "Invalid" 1 "Power down normally" 2 "Force to power down" 3 "Reserved" ;
VAL_ 2148695982 M2S_CMD2_FanCtrl_30 0 "Fan Off" 1 "Fan On" ;
VAL_ 2148695982 M2S_CMD2_Data3_30 250 "报换故障清除" 255 "所有故障清除指令" ;
VAL_ 2148695982 M2S_CMD2_FullChgFlgFromMBMU_30 0 "未满充修正" 21 "满充修正" ;
VAL_ 2148695983 M2S_CMD2_PowerDown_31 0 "Invalid" 1 "Power down normally" 2 "Force to power down" 3 "Reserved" ;
VAL_ 2148695983 M2S_CMD2_FanCtrl_31 0 "Fan Off" 1 "Fan On" ;
VAL_ 2148695983 M2S_CMD2_Data3_31 250 "报换故障清除" 255 "所有故障清除指令" ;
VAL_ 2148695983 M2S_CMD2_FullChgFlgFromMBMU_31 0 "未满充修正" 21 "满充修正" ;
VAL_ 2148761489 M2S_CMD3_TankNo_01 65 "Tank1" 66 "Tank2" 67 "Tank3" 68 "Tank4" 255 "All Tank" ;
VAL_ 2148761489 M2S_CMD3_TankSOC_01 65535 "Invalid" ;
VAL_ 2148761489 M2S_CMD3_SOCCmd_01 0 "更新最大、最小和显示SOC" 1 "更新最大和最小SOC" 2 "更新最大SOC " 3 "更新最小SOC" ;
VAL_ 2148761490 M2S_CMD3_TankNo_02 65 "Tank1" 66 "Tank2" 67 "Tank3" 68 "Tank4" 255 "All Tank" ;
VAL_ 2148761490 M2S_CMD3_TankSOC_02 65535 "Invalid" ;
VAL_ 2148761490 M2S_CMD3_SOCCmd_02 0 "更新最大、最小和显示SOC" 1 "更新最大和最小SOC" 2 "更新最大SOC " 3 "更新最小SOC" ;
VAL_ 2148761491 M2S_CMD3_TankNo_03 65 "Tank1" 66 "Tank2" 67 "Tank3" 68 "Tank4" 255 "All Tank" ;
VAL_ 2148761491 M2S_CMD3_TankSOC_03 65535 "Invalid" ;
VAL_ 2148761491 M2S_CMD3_SOCCmd_03 0 "更新最大、最小和显示SOC" 1 "更新最大和最小SOC" 2 "更新最大SOC " 3 "更新最小SOC" ;
VAL_ 2148761492 M2S_CMD3_TankNo_04 65 "Tank1" 66 "Tank2" 67 "Tank3" 68 "Tank4" 255 "All Tank" ;
VAL_ 2148761492 M2S_CMD3_TankSOC_04 65535 "Invalid" ;
VAL_ 2148761492 M2S_CMD3_SOCCmd_04 0 "更新最大、最小和显示SOC" 1 "更新最大和最小SOC" 2 "更新最大SOC " 3 "更新最小SOC" ;
VAL_ 2148761493 M2S_CMD3_TankNo_05 65 "Tank1" 66 "Tank2" 67 "Tank3" 68 "Tank4" 255 "All Tank" ;
VAL_ 2148761493 M2S_CMD3_TankSOC_05 65535 "Invalid" ;
VAL_ 2148761493 M2S_CMD3_SOCCmd_05 0 "更新最大、最小和显示SOC" 1 "更新最大和最小SOC" 2 "更新最大SOC " 3 "更新最小SOC" ;
VAL_ 2148761494 M2S_CMD3_TankNo_06 65 "Tank1" 66 "Tank2" 67 "Tank3" 68 "Tank4" 255 "All Tank" ;
VAL_ 2148761494 M2S_CMD3_TankSOC_06 65535 "Invalid" ;
VAL_ 2148761494 M2S_CMD3_SOCCmd_06 0 "更新最大、最小和显示SOC" 1 "更新最大和最小SOC" 2 "更新最大SOC " 3 "更新最小SOC" ;
VAL_ 2148761495 M2S_CMD3_TankNo_07 65 "Tank1" 66 "Tank2" 67 "Tank3" 68 "Tank4" 255 "All Tank" ;
VAL_ 2148761495 M2S_CMD3_TankSOC_07 65535 "Invalid" ;
VAL_ 2148761495 M2S_CMD3_SOCCmd_07 0 "更新最大、最小和显示SOC" 1 "更新最大和最小SOC" 2 "更新最大SOC " 3 "更新最小SOC" ;
VAL_ 2148761496 M2S_CMD3_TankNo_08 65 "Tank1" 66 "Tank2" 67 "Tank3" 68 "Tank4" 255 "All Tank" ;
VAL_ 2148761496 M2S_CMD3_TankSOC_08 65535 "Invalid" ;
VAL_ 2148761496 M2S_CMD3_SOCCmd_08 0 "更新最大、最小和显示SOC" 1 "更新最大和最小SOC" 2 "更新最大SOC " 3 "更新最小SOC" ;
VAL_ 2148761497 M2S_CMD3_TankNo_09 65 "Tank1" 66 "Tank2" 67 "Tank3" 68 "Tank4" 255 "All Tank" ;
VAL_ 2148761497 M2S_CMD3_TankSOC_09 65535 "Invalid" ;
VAL_ 2148761497 M2S_CMD3_SOCCmd_09 0 "更新最大、最小和显示SOC" 1 "更新最大和最小SOC" 2 "更新最大SOC " 3 "更新最小SOC" ;
VAL_ 2148761498 M2S_CMD3_TankNo_10 65 "Tank1" 66 "Tank2" 67 "Tank3" 68 "Tank4" 255 "All Tank" ;
VAL_ 2148761498 M2S_CMD3_TankSOC_10 65535 "Invalid" ;
VAL_ 2148761498 M2S_CMD3_SOCCmd_10 0 "更新最大、最小和显示SOC" 1 "更新最大和最小SOC" 2 "更新最大SOC " 3 "更新最小SOC" ;
VAL_ 2148761499 M2S_CMD3_TankNo_11 65 "Tank1" 66 "Tank2" 67 "Tank3" 68 "Tank4" 255 "All Tank" ;
VAL_ 2148761499 M2S_CMD3_TankSOC_11 65535 "Invalid" ;
VAL_ 2148761499 M2S_CMD3_SOCCmd_11 0 "更新最大、最小和显示SOC" 1 "更新最大和最小SOC" 2 "更新最大SOC " 3 "更新最小SOC" ;
VAL_ 2148761500 M2S_CMD3_TankNo_12 65 "Tank1" 66 "Tank2" 67 "Tank3" 68 "Tank4" 255 "All Tank" ;
VAL_ 2148761500 M2S_CMD3_TankSOC_12 65535 "Invalid" ;
VAL_ 2148761500 M2S_CMD3_SOCCmd_12 0 "更新最大、最小和显示SOC" 1 "更新最大和最小SOC" 2 "更新最大SOC " 3 "更新最小SOC" ;
VAL_ 2148761501 M2S_CMD3_TankNo_13 65 "Tank1" 66 "Tank2" 67 "Tank3" 68 "Tank4" 255 "All Tank" ;
VAL_ 2148761501 M2S_CMD3_TankSOC_13 65535 "Invalid" ;
VAL_ 2148761501 M2S_CMD3_SOCCmd_13 0 "更新最大、最小和显示SOC" 1 "更新最大和最小SOC" 2 "更新最大SOC " 3 "更新最小SOC" ;
VAL_ 2148761502 M2S_CMD3_TankNo_14 65 "Tank1" 66 "Tank2" 67 "Tank3" 68 "Tank4" 255 "All Tank" ;
VAL_ 2148761502 M2S_CMD3_TankSOC_14 65535 "Invalid" ;
VAL_ 2148761502 M2S_CMD3_SOCCmd_14 0 "更新最大、最小和显示SOC" 1 "更新最大和最小SOC" 2 "更新最大SOC " 3 "更新最小SOC" ;
VAL_ 2148761503 M2S_CMD3_TankNo_15 65 "Tank1" 66 "Tank2" 67 "Tank3" 68 "Tank4" 255 "All Tank" ;
VAL_ 2148761503 M2S_CMD3_TankSOC_15 65535 "Invalid" ;
VAL_ 2148761503 M2S_CMD3_SOCCmd_15 0 "更新最大、最小和显示SOC" 1 "更新最大和最小SOC" 2 "更新最大SOC " 3 "更新最小SOC" ;
VAL_ 2148761504 M2S_CMD3_TankNo_16 65 "Tank1" 66 "Tank2" 67 "Tank3" 68 "Tank4" 255 "All Tank" ;
VAL_ 2148761504 M2S_CMD3_TankSOC_16 65535 "Invalid" ;
VAL_ 2148761504 M2S_CMD3_SOCCmd_16 0 "更新最大、最小和显示SOC" 1 "更新最大和最小SOC" 2 "更新最大SOC " 3 "更新最小SOC" ;
VAL_ 2148761505 M2S_CMD3_TankNo_17 65 "Tank1" 66 "Tank2" 67 "Tank3" 68 "Tank4" 255 "All Tank" ;
VAL_ 2148761505 M2S_CMD3_TankSOC_17 65535 "Invalid" ;
VAL_ 2148761505 M2S_CMD3_SOCCmd_17 0 "更新最大、最小和显示SOC" 1 "更新最大和最小SOC" 2 "更新最大SOC " 3 "更新最小SOC" ;
VAL_ 2148761506 M2S_CMD3_TankNo_18 65 "Tank1" 66 "Tank2" 67 "Tank3" 68 "Tank4" 255 "All Tank" ;
VAL_ 2148761506 M2S_CMD3_TankSOC_18 65535 "Invalid" ;
VAL_ 2148761506 M2S_CMD3_SOCCmd_18 0 "更新最大、最小和显示SOC" 1 "更新最大和最小SOC" 2 "更新最大SOC " 3 "更新最小SOC" ;
VAL_ 2148761507 M2S_CMD3_TankNo_19 65 "Tank1" 66 "Tank2" 67 "Tank3" 68 "Tank4" 255 "All Tank" ;
VAL_ 2148761507 M2S_CMD3_TankSOC_19 65535 "Invalid" ;
VAL_ 2148761507 M2S_CMD3_SOCCmd_19 0 "更新最大、最小和显示SOC" 1 "更新最大和最小SOC" 2 "更新最大SOC " 3 "更新最小SOC" ;
VAL_ 2148761508 M2S_CMD3_TankNo_20 65 "Tank1" 66 "Tank2" 67 "Tank3" 68 "Tank4" 255 "All Tank" ;
VAL_ 2148761508 M2S_CMD3_TankSOC_20 65535 "Invalid" ;
VAL_ 2148761508 M2S_CMD3_SOCCmd_20 0 "更新最大、最小和显示SOC" 1 "更新最大和最小SOC" 2 "更新最大SOC " 3 "更新最小SOC" ;
VAL_ 2148761509 M2S_CMD3_TankNo_21 65 "Tank1" 66 "Tank2" 67 "Tank3" 68 "Tank4" 255 "All Tank" ;
VAL_ 2148761509 M2S_CMD3_TankSOC_21 65535 "Invalid" ;
VAL_ 2148761509 M2S_CMD3_SOCCmd_21 0 "更新最大、最小和显示SOC" 1 "更新最大和最小SOC" 2 "更新最大SOC " 3 "更新最小SOC" ;
VAL_ 2148761510 M2S_CMD3_TankNo_22 65 "Tank1" 66 "Tank2" 67 "Tank3" 68 "Tank4" 255 "All Tank" ;
VAL_ 2148761510 M2S_CMD3_TankSOC_22 65535 "Invalid" ;
VAL_ 2148761510 M2S_CMD3_SOCCmd_22 0 "更新最大、最小和显示SOC" 1 "更新最大和最小SOC" 2 "更新最大SOC " 3 "更新最小SOC" ;
VAL_ 2148761511 M2S_CMD3_TankNo_23 65 "Tank1" 66 "Tank2" 67 "Tank3" 68 "Tank4" 255 "All Tank" ;
VAL_ 2148761511 M2S_CMD3_TankSOC_23 65535 "Invalid" ;
VAL_ 2148761511 M2S_CMD3_SOCCmd_23 0 "更新最大、最小和显示SOC" 1 "更新最大和最小SOC" 2 "更新最大SOC " 3 "更新最小SOC" ;
VAL_ 2148761512 M2S_CMD3_TankNo_24 65 "Tank1" 66 "Tank2" 67 "Tank3" 68 "Tank4" 255 "All Tank" ;
VAL_ 2148761512 M2S_CMD3_TankSOC_24 65535 "Invalid" ;
VAL_ 2148761512 M2S_CMD3_SOCCmd_24 0 "更新最大、最小和显示SOC" 1 "更新最大和最小SOC" 2 "更新最大SOC " 3 "更新最小SOC" ;
VAL_ 2148761513 M2S_CMD3_TankNo_25 65 "Tank1" 66 "Tank2" 67 "Tank3" 68 "Tank4" 255 "All Tank" ;
VAL_ 2148761513 M2S_CMD3_TankSOC_25 65535 "Invalid" ;
VAL_ 2148761513 M2S_CMD3_SOCCmd_25 0 "更新最大、最小和显示SOC" 1 "更新最大和最小SOC" 2 "更新最大SOC " 3 "更新最小SOC" ;
VAL_ 2148761514 M2S_CMD3_TankNo_26 65 "Tank1" 66 "Tank2" 67 "Tank3" 68 "Tank4" 255 "All Tank" ;
VAL_ 2148761514 M2S_CMD3_TankSOC_26 65535 "Invalid" ;
VAL_ 2148761514 M2S_CMD3_SOCCmd_26 0 "更新最大、最小和显示SOC" 1 "更新最大和最小SOC" 2 "更新最大SOC " 3 "更新最小SOC" ;
VAL_ 2148761515 M2S_CMD3_TankNo_27 65 "Tank1" 66 "Tank2" 67 "Tank3" 68 "Tank4" 255 "All Tank" ;
VAL_ 2148761515 M2S_CMD3_TankSOC_27 65535 "Invalid" ;
VAL_ 2148761515 M2S_CMD3_SOCCmd_27 0 "更新最大、最小和显示SOC" 1 "更新最大和最小SOC" 2 "更新最大SOC " 3 "更新最小SOC" ;
VAL_ 2148761516 M2S_CMD3_TankNo_28 65 "Tank1" 66 "Tank2" 67 "Tank3" 68 "Tank4" 255 "All Tank" ;
VAL_ 2148761516 M2S_CMD3_TankSOC_28 65535 "Invalid" ;
VAL_ 2148761516 M2S_CMD3_SOCCmd_28 0 "更新最大、最小和显示SOC" 1 "更新最大和最小SOC" 2 "更新最大SOC " 3 "更新最小SOC" ;
VAL_ 2148761517 M2S_CMD3_TankNo_29 65 "Tank1" 66 "Tank2" 67 "Tank3" 68 "Tank4" 255 "All Tank" ;
VAL_ 2148761517 M2S_CMD3_TankSOC_29 65535 "Invalid" ;
VAL_ 2148761517 M2S_CMD3_SOCCmd_29 0 "更新最大、最小和显示SOC" 1 "更新最大和最小SOC" 2 "更新最大SOC " 3 "更新最小SOC" ;
VAL_ 2148761518 M2S_CMD3_TankNo_30 65 "Tank1" 66 "Tank2" 67 "Tank3" 68 "Tank4" 255 "All Tank" ;
VAL_ 2148761518 M2S_CMD3_TankSOC_30 65535 "Invalid" ;
VAL_ 2148761518 M2S_CMD3_SOCCmd_30 0 "更新最大、最小和显示SOC" 1 "更新最大和最小SOC" 2 "更新最大SOC " 3 "更新最小SOC" ;
VAL_ 2148761519 M2S_CMD3_TankNo_31 65 "Tank1" 66 "Tank2" 67 "Tank3" 68 "Tank4" 255 "All Tank" ;
VAL_ 2148761519 M2S_CMD3_TankSOC_31 65535 "Invalid" ;
VAL_ 2148761519 M2S_CMD3_SOCCmd_31 0 "更新最大、最小和显示SOC" 1 "更新最大和最小SOC" 2 "更新最大SOC " 3 "更新最小SOC" ;
VERSION ""

NS_ :

BS_:

BU_: MBMU PC SBMU IMM ETH DCDC LEMS

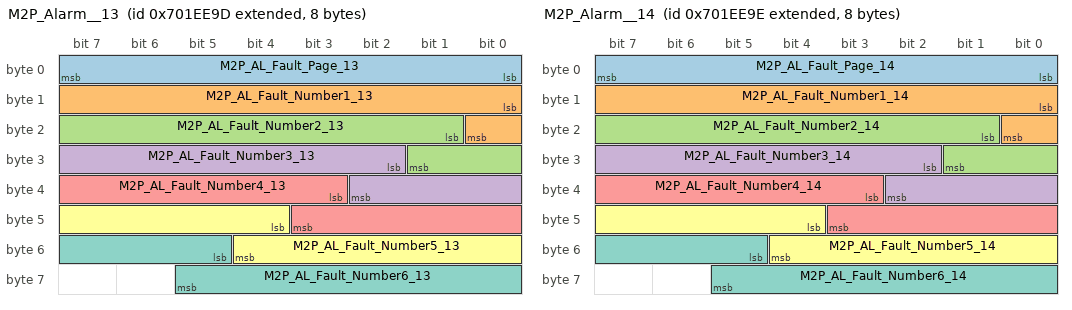
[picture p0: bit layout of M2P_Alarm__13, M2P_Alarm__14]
BO_ 2265050781 M2P_Alarm__13: 8 MBMU
 SG_ M2P_AL_Fault_Page_13 : 0|8@1+ (1,0) [0|255] ""  PC
 SG_ M2P_AL_Fault_Number1_13 : 8|9@1+ (1,0) [0|511] ""  PC
 SG_ M2P_AL_Fault_Number2_13 : 17|9@1+ (1,0) [0|511] ""  PC
 SG_ M2P_AL_Fault_Number3_13 : 26|9@1+ (1,0) [0|511] ""  PC
 SG_ M2P_AL_Fault_Number4_13 : 35|9@1+ (1,0) [0|511] ""  PC
 SG_ M2P_AL_Fault_Number5_13 : 44|9@1+ (1,0) [0|511] ""  PC
 SG_ M2P_AL_Fault_Number6_13 : 53|9@1+ (1,0) [0|511] ""  PC

BO_ 2265050782 M2P_Alarm__14: 8 MBMU
 SG_ M2P_AL_Fault_Page_14 : 0|8@1+ (1,0) [0|255] ""  PC
 SG_ M2P_AL_Fault_Number1_14 : 8|9@1+ (1,0) [0|511] ""  PC
 SG_ M2P_AL_Fault_Number2_14 : 17|9@1+ (1,0) [0|511] ""  PC
 SG_ M2P_AL_Fault_Number3_14 : 26|9@1+ (1,0) [0|511] ""  PC
 SG_ M2P_AL_Fault_Number4_14 : 35|9@1+ (1,0) [0|511] ""  PC
 SG_ M2P_AL_Fault_Number5_14 : 44|9@1+ (1,0) [0|511] ""  PC
 SG_ M2P_AL_Fault_Number6_14 : 53|9@1+ (1,0) [0|511] ""  PC

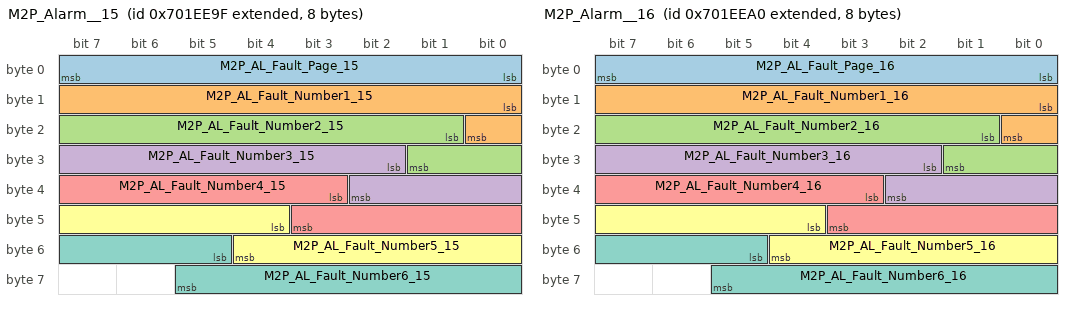
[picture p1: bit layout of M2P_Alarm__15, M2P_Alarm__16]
BO_ 2265050783 M2P_Alarm__15: 8 MBMU
 SG_ M2P_AL_Fault_Page_15 : 0|8@1+ (1,0) [0|255] ""  PC
 SG_ M2P_AL_Fault_Number1_15 : 8|9@1+ (1,0) [0|511] ""  PC
 SG_ M2P_AL_Fault_Number2_15 : 17|9@1+ (1,0) [0|511] ""  PC
 SG_ M2P_AL_Fault_Number3_15 : 26|9@1+ (1,0) [0|511] ""  PC
 SG_ M2P_AL_Fault_Number4_15 : 35|9@1+ (1,0) [0|511] ""  PC
 SG_ M2P_AL_Fault_Number5_15 : 44|9@1+ (1,0) [0|511] ""  PC
 SG_ M2P_AL_Fault_Number6_15 : 53|9@1+ (1,0) [0|511] ""  PC

BO_ 2265050784 M2P_Alarm__16: 8 MBMU
 SG_ M2P_AL_Fault_Page_16 : 0|8@1+ (1,0) [0|255] ""  PC
 SG_ M2P_AL_Fault_Number1_16 : 8|9@1+ (1,0) [0|511] ""  PC
 SG_ M2P_AL_Fault_Number2_16 : 17|9@1+ (1,0) [0|511] ""  PC
 SG_ M2P_AL_Fault_Number3_16 : 26|9@1+ (1,0) [0|511] ""  PC
 SG_ M2P_AL_Fault_Number4_16 : 35|9@1+ (1,0) [0|511] ""  PC
 SG_ M2P_AL_Fault_Number5_16 : 44|9@1+ (1,0) [0|511] ""  PC
 SG_ M2P_AL_Fault_Number6_16 : 53|9@1+ (1,0) [0|511] ""  PC

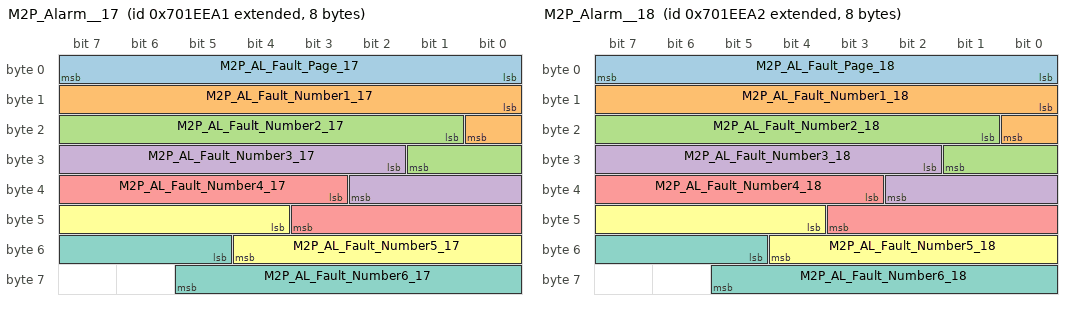
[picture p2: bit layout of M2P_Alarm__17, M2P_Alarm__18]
BO_ 2265050785 M2P_Alarm__17: 8 MBMU
 SG_ M2P_AL_Fault_Page_17 : 0|8@1+ (1,0) [0|255] ""  PC
 SG_ M2P_AL_Fault_Number1_17 : 8|9@1+ (1,0) [0|511] ""  PC
 SG_ M2P_AL_Fault_Number2_17 : 17|9@1+ (1,0) [0|511] ""  PC
 SG_ M2P_AL_Fault_Number3_17 : 26|9@1+ (1,0) [0|511] ""  PC
 SG_ M2P_AL_Fault_Number4_17 : 35|9@1+ (1,0) [0|511] ""  PC
 SG_ M2P_AL_Fault_Number5_17 : 44|9@1+ (1,0) [0|511] ""  PC
 SG_ M2P_AL_Fault_Number6_17 : 53|9@1+ (1,0) [0|511] ""  PC

BO_ 2265050786 M2P_Alarm__18: 8 MBMU
 SG_ M2P_AL_Fault_Page_18 : 0|8@1+ (1,0) [0|255] ""  PC
 SG_ M2P_AL_Fault_Number1_18 : 8|9@1+ (1,0) [0|511] ""  PC
 SG_ M2P_AL_Fault_Number2_18 : 17|9@1+ (1,0) [0|511] ""  PC
 SG_ M2P_AL_Fault_Number3_18 : 26|9@1+ (1,0) [0|511] ""  PC
 SG_ M2P_AL_Fault_Number4_18 : 35|9@1+ (1,0) [0|511] ""  PC
 SG_ M2P_AL_Fault_Number5_18 : 44|9@1+ (1,0) [0|511] ""  PC
 SG_ M2P_AL_Fault_Number6_18 : 53|9@1+ (1,0) [0|511] ""  PC

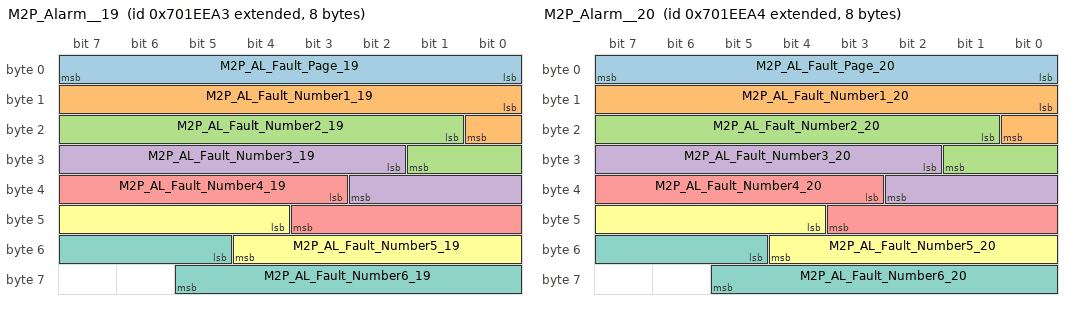
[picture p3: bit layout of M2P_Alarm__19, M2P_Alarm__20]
BO_ 2265050787 M2P_Alarm__19: 8 MBMU
 SG_ M2P_AL_Fault_Page_19 : 0|8@1+ (1,0) [0|255] ""  PC
 SG_ M2P_AL_Fault_Number1_19 : 8|9@1+ (1,0) [0|511] ""  PC
 SG_ M2P_AL_Fault_Number2_19 : 17|9@1+ (1,0) [0|511] ""  PC
 SG_ M2P_AL_Fault_Number3_19 : 26|9@1+ (1,0) [0|511] ""  PC
 SG_ M2P_AL_Fault_Number4_19 : 35|9@1+ (1,0) [0|511] ""  PC
 SG_ M2P_AL_Fault_Number5_19 : 44|9@1+ (1,0) [0|511] ""  PC
 SG_ M2P_AL_Fault_Number6_19 : 53|9@1+ (1,0) [0|511] ""  PC

BO_ 2265050788 M2P_Alarm__20: 8 MBMU
 SG_ M2P_AL_Fault_Page_20 : 0|8@1+ (1,0) [0|255] ""  PC
 SG_ M2P_AL_Fault_Number1_20 : 8|9@1+ (1,0) [0|511] ""  PC
 SG_ M2P_AL_Fault_Number2_20 : 17|9@1+ (1,0) [0|511] ""  PC
 SG_ M2P_AL_Fault_Number3_20 : 26|9@1+ (1,0) [0|511] ""  PC
 SG_ M2P_AL_Fault_Number4_20 : 35|9@1+ (1,0) [0|511] ""  PC
 SG_ M2P_AL_Fault_Number5_20 : 44|9@1+ (1,0) [0|511] ""  PC
 SG_ M2P_AL_Fault_Number6_20 : 53|9@1+ (1,0) [0|511] ""  PC

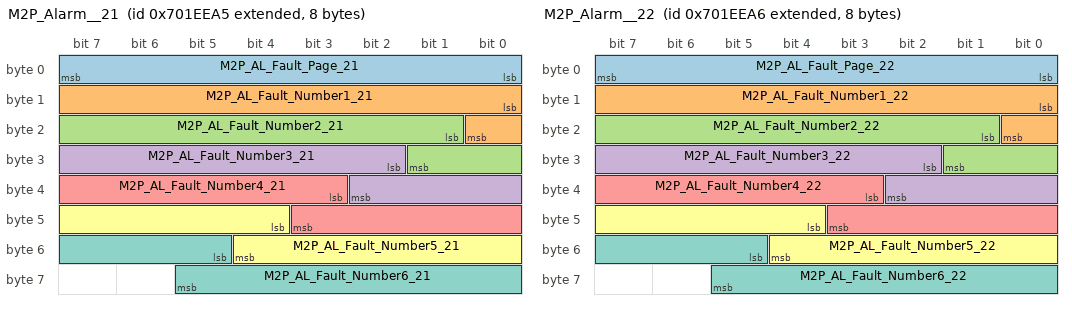
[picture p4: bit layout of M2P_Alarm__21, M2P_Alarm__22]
BO_ 2265050789 M2P_Alarm__21: 8 MBMU
 SG_ M2P_AL_Fault_Page_21 : 0|8@1+ (1,0) [0|255] ""  PC
 SG_ M2P_AL_Fault_Number1_21 : 8|9@1+ (1,0) [0|511] ""  PC
 SG_ M2P_AL_Fault_Number2_21 : 17|9@1+ (1,0) [0|511] ""  PC
 SG_ M2P_AL_Fault_Number3_21 : 26|9@1+ (1,0) [0|511] ""  PC
 SG_ M2P_AL_Fault_Number4_21 : 35|9@1+ (1,0) [0|511] ""  PC
 SG_ M2P_AL_Fault_Number5_21 : 44|9@1+ (1,0) [0|511] ""  PC
 SG_ M2P_AL_Fault_Number6_21 : 53|9@1+ (1,0) [0|511] ""  PC

BO_ 2265050790 M2P_Alarm__22: 8 MBMU
 SG_ M2P_AL_Fault_Page_22 : 0|8@1+ (1,0) [0|255] ""  PC
 SG_ M2P_AL_Fault_Number1_22 : 8|9@1+ (1,0) [0|511] ""  PC
 SG_ M2P_AL_Fault_Number2_22 : 17|9@1+ (1,0) [0|511] ""  PC
 SG_ M2P_AL_Fault_Number3_22 : 26|9@1+ (1,0) [0|511] ""  PC
 SG_ M2P_AL_Fault_Number4_22 : 35|9@1+ (1,0) [0|511] ""  PC
 SG_ M2P_AL_Fault_Number5_22 : 44|9@1+ (1,0) [0|511] ""  PC
 SG_ M2P_AL_Fault_Number6_22 : 53|9@1+ (1,0) [0|511] ""  PC

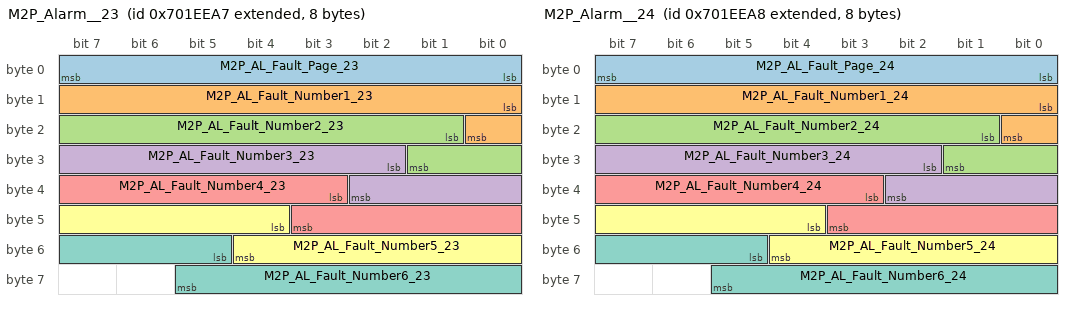
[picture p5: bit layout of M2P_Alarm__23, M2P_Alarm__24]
BO_ 2265050791 M2P_Alarm__23: 8 MBMU
 SG_ M2P_AL_Fault_Page_23 : 0|8@1+ (1,0) [0|255] ""  PC
 SG_ M2P_AL_Fault_Number1_23 : 8|9@1+ (1,0) [0|511] ""  PC
 SG_ M2P_AL_Fault_Number2_23 : 17|9@1+ (1,0) [0|511] ""  PC
 SG_ M2P_AL_Fault_Number3_23 : 26|9@1+ (1,0) [0|511] ""  PC
 SG_ M2P_AL_Fault_Number4_23 : 35|9@1+ (1,0) [0|511] ""  PC
 SG_ M2P_AL_Fault_Number5_23 : 44|9@1+ (1,0) [0|511] ""  PC
 SG_ M2P_AL_Fault_Number6_23 : 53|9@1+ (1,0) [0|511] ""  PC

BO_ 2265050792 M2P_Alarm__24: 8 MBMU
 SG_ M2P_AL_Fault_Page_24 : 0|8@1+ (1,0) [0|255] ""  PC
 SG_ M2P_AL_Fault_Number1_24 : 8|9@1+ (1,0) [0|511] ""  PC
 SG_ M2P_AL_Fault_Number2_24 : 17|9@1+ (1,0) [0|511] ""  PC
 SG_ M2P_AL_Fault_Number3_24 : 26|9@1+ (1,0) [0|511] ""  PC
 SG_ M2P_AL_Fault_Number4_24 : 35|9@1+ (1,0) [0|511] ""  PC
 SG_ M2P_AL_Fault_Number5_24 : 44|9@1+ (1,0) [0|511] ""  PC
 SG_ M2P_AL_Fault_Number6_24 : 53|9@1+ (1,0) [0|511] ""  PC

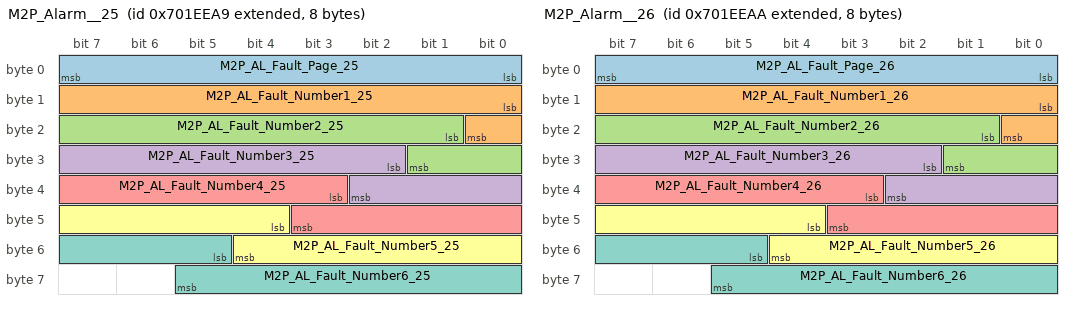
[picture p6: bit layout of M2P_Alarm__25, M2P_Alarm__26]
BO_ 2265050793 M2P_Alarm__25: 8 MBMU
 SG_ M2P_AL_Fault_Page_25 : 0|8@1+ (1,0) [0|255] ""  PC
 SG_ M2P_AL_Fault_Number1_25 : 8|9@1+ (1,0) [0|511] ""  PC
 SG_ M2P_AL_Fault_Number2_25 : 17|9@1+ (1,0) [0|511] ""  PC
 SG_ M2P_AL_Fault_Number3_25 : 26|9@1+ (1,0) [0|511] ""  PC
 SG_ M2P_AL_Fault_Number4_25 : 35|9@1+ (1,0) [0|511] ""  PC
 SG_ M2P_AL_Fault_Number5_25 : 44|9@1+ (1,0) [0|511] ""  PC
 SG_ M2P_AL_Fault_Number6_25 : 53|9@1+ (1,0) [0|511] ""  PC

BO_ 2265050794 M2P_Alarm__26: 8 MBMU
 SG_ M2P_AL_Fault_Page_26 : 0|8@1+ (1,0) [0|255] ""  PC
 SG_ M2P_AL_Fault_Number1_26 : 8|9@1+ (1,0) [0|511] ""  PC
 SG_ M2P_AL_Fault_Number2_26 : 17|9@1+ (1,0) [0|511] ""  PC
 SG_ M2P_AL_Fault_Number3_26 : 26|9@1+ (1,0) [0|511] ""  PC
 SG_ M2P_AL_Fault_Number4_26 : 35|9@1+ (1,0) [0|511] ""  PC
 SG_ M2P_AL_Fault_Number5_26 : 44|9@1+ (1,0) [0|511] ""  PC
 SG_ M2P_AL_Fault_Number6_26 : 53|9@1+ (1,0) [0|511] ""  PC

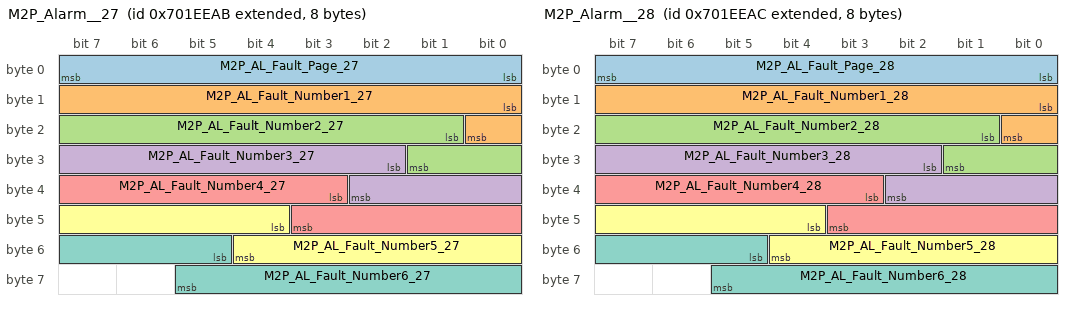
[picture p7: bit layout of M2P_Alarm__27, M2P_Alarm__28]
BO_ 2265050795 M2P_Alarm__27: 8 MBMU
 SG_ M2P_AL_Fault_Page_27 : 0|8@1+ (1,0) [0|255] ""  PC
 SG_ M2P_AL_Fault_Number1_27 : 8|9@1+ (1,0) [0|511] ""  PC
 SG_ M2P_AL_Fault_Number2_27 : 17|9@1+ (1,0) [0|511] ""  PC
 SG_ M2P_AL_Fault_Number3_27 : 26|9@1+ (1,0) [0|511] ""  PC
 SG_ M2P_AL_Fault_Number4_27 : 35|9@1+ (1,0) [0|511] ""  PC
 SG_ M2P_AL_Fault_Number5_27 : 44|9@1+ (1,0) [0|511] ""  PC
 SG_ M2P_AL_Fault_Number6_27 : 53|9@1+ (1,0) [0|511] ""  PC

BO_ 2265050796 M2P_Alarm__28: 8 MBMU
 SG_ M2P_AL_Fault_Page_28 : 0|8@1+ (1,0) [0|255] ""  PC
 SG_ M2P_AL_Fault_Number1_28 : 8|9@1+ (1,0) [0|511] ""  PC
 SG_ M2P_AL_Fault_Number2_28 : 17|9@1+ (1,0) [0|511] ""  PC
 SG_ M2P_AL_Fault_Number3_28 : 26|9@1+ (1,0) [0|511] ""  PC
 SG_ M2P_AL_Fault_Number4_28 : 35|9@1+ (1,0) [0|511] ""  PC
 SG_ M2P_AL_Fault_Number5_28 : 44|9@1+ (1,0) [0|511] ""  PC
 SG_ M2P_AL_Fault_Number6_28 : 53|9@1+ (1,0) [0|511] ""  PC

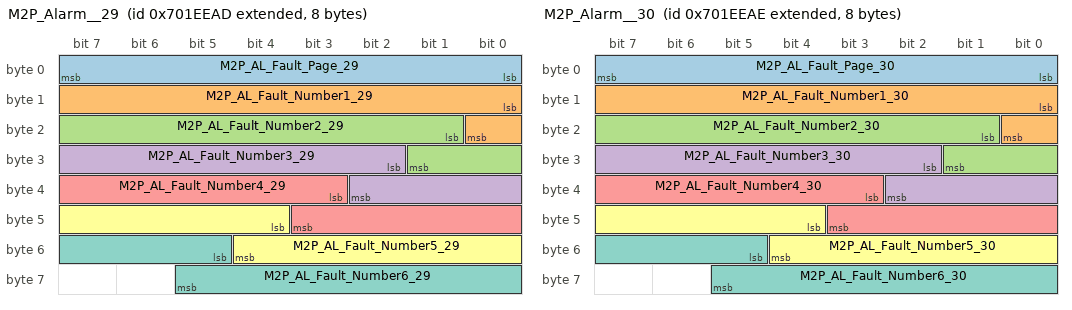
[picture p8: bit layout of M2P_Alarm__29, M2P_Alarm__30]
BO_ 2265050797 M2P_Alarm__29: 8 MBMU
 SG_ M2P_AL_Fault_Page_29 : 0|8@1+ (1,0) [0|255] ""  PC
 SG_ M2P_AL_Fault_Number1_29 : 8|9@1+ (1,0) [0|511] ""  PC
 SG_ M2P_AL_Fault_Number2_29 : 17|9@1+ (1,0) [0|511] ""  PC
 SG_ M2P_AL_Fault_Number3_29 : 26|9@1+ (1,0) [0|511] ""  PC
 SG_ M2P_AL_Fault_Number4_29 : 35|9@1+ (1,0) [0|511] ""  PC
 SG_ M2P_AL_Fault_Number5_29 : 44|9@1+ (1,0) [0|511] ""  PC
 SG_ M2P_AL_Fault_Number6_29 : 53|9@1+ (1,0) [0|511] ""  PC

BO_ 2265050798 M2P_Alarm__30: 8 MBMU
 SG_ M2P_AL_Fault_Page_30 : 0|8@1+ (1,0) [0|255] ""  PC
 SG_ M2P_AL_Fault_Number1_30 : 8|9@1+ (1,0) [0|511] ""  PC
 SG_ M2P_AL_Fault_Number2_30 : 17|9@1+ (1,0) [0|511] ""  PC
 SG_ M2P_AL_Fault_Number3_30 : 26|9@1+ (1,0) [0|511] ""  PC
 SG_ M2P_AL_Fault_Number4_30 : 35|9@1+ (1,0) [0|511] ""  PC
 SG_ M2P_AL_Fault_Number5_30 : 44|9@1+ (1,0) [0|511] ""  PC
 SG_ M2P_AL_Fault_Number6_30 : 53|9@1+ (1,0) [0|511] ""  PC

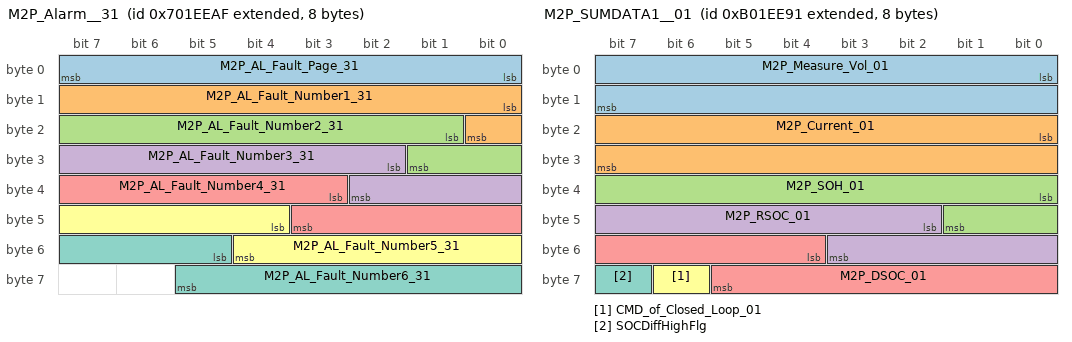
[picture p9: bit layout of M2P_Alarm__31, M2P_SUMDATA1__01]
BO_ 2265050799 M2P_Alarm__31: 8 MBMU
 SG_ M2P_AL_Fault_Page_31 : 0|8@1+ (1,0) [0|255] ""  PC
 SG_ M2P_AL_Fault_Number1_31 : 8|9@1+ (1,0) [0|511] ""  PC
 SG_ M2P_AL_Fault_Number2_31 : 17|9@1+ (1,0) [0|511] ""  PC
 SG_ M2P_AL_Fault_Number3_31 : 26|9@1+ (1,0) [0|511] ""  PC
 SG_ M2P_AL_Fault_Number4_31 : 35|9@1+ (1,0) [0|511] ""  PC
 SG_ M2P_AL_Fault_Number5_31 : 44|9@1+ (1,0) [0|511] ""  PC
 SG_ M2P_AL_Fault_Number6_31 : 53|9@1+ (1,0) [0|511] ""  PC

BO_ 2332159633 M2P_SUMDATA1__01: 8 MBMU
 SG_ M2P_Measure_Vol_01 : 0|16@1+ (0.1,0) [0|6553.5] "V"  PC,SBMU
 SG_ M2P_Current_01 : 16|16@1+ (1,-20000) [-20000|45535] "A"  PC,SBMU
 SG_ M2P_SOH_01 : 32|10@1+ (0.1,0) [0|102.3] "%"  PC,SBMU
 SG_ M2P_RSOC_01 : 42|10@1+ (0.1,0) [0|102.3] "%"  PC,SBMU
 SG_ M2P_DSOC_01 : 52|10@1+ (0.1,0) [0|102.3] "%"  PC,SBMU
 SG_ CMD_of_Closed_Loop_01 : 62|1@1+ (1,0) [0|1] ""  PC,SBMU
 SG_ SOCDiffHighFlg : 63|1@1+ (1,0) [0|1] ""  PC,SBMU

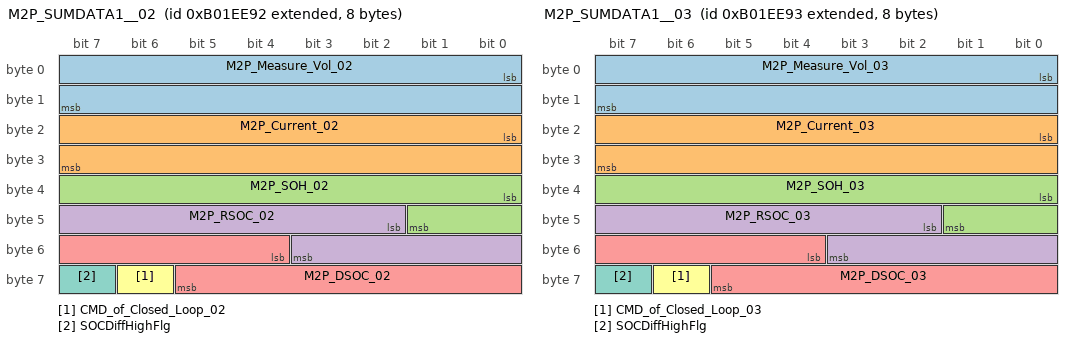
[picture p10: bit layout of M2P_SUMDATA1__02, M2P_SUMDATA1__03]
BO_ 2332159634 M2P_SUMDATA1__02: 8 MBMU
 SG_ M2P_Measure_Vol_02 : 0|16@1+ (0.1,0) [0|6553.5] "V"  PC,SBMU
 SG_ M2P_Current_02 : 16|16@1+ (1,-20000) [-20000|45535] "A"  PC,SBMU
 SG_ M2P_SOH_02 : 32|10@1+ (0.1,0) [0|102.3] "%"  PC,SBMU
 SG_ M2P_RSOC_02 : 42|10@1+ (0.1,0) [0|102.3] "%"  PC,SBMU
 SG_ M2P_DSOC_02 : 52|10@1+ (0.1,0) [0|102.3] "%"  PC,SBMU
 SG_ CMD_of_Closed_Loop_02 : 62|1@1+ (1,0) [0|1] ""  PC,SBMU
 SG_ SOCDiffHighFlg : 63|1@1+ (1,0) [0|1] ""  PC,SBMU

BO_ 2332159635 M2P_SUMDATA1__03: 8 MBMU
 SG_ M2P_Measure_Vol_03 : 0|16@1+ (0.1,0) [0|6553.5] "V"  PC,SBMU
 SG_ M2P_Current_03 : 16|16@1+ (1,-20000) [-20000|45535] "A"  PC,SBMU
 SG_ M2P_SOH_03 : 32|10@1+ (0.1,0) [0|102.3] "%"  PC,SBMU
 SG_ M2P_RSOC_03 : 42|10@1+ (0.1,0) [0|102.3] "%"  PC,SBMU
 SG_ M2P_DSOC_03 : 52|10@1+ (0.1,0) [0|102.3] "%"  PC,SBMU
 SG_ CMD_of_Closed_Loop_03 : 62|1@1+ (1,0) [0|1] ""  PC,SBMU
 SG_ SOCDiffHighFlg : 63|1@1+ (1,0) [0|1] ""  PC,SBMU

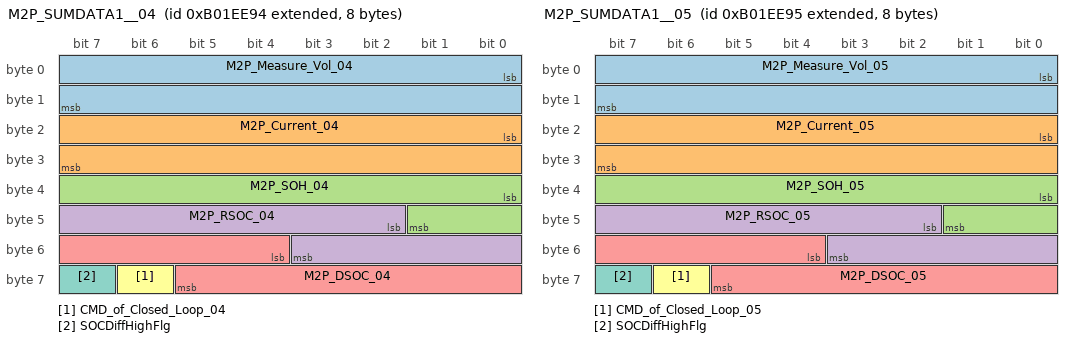
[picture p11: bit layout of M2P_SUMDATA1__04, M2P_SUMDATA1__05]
BO_ 2332159636 M2P_SUMDATA1__04: 8 MBMU
 SG_ M2P_Measure_Vol_04 : 0|16@1+ (0.1,0) [0|6553.5] "V"  PC,SBMU
 SG_ M2P_Current_04 : 16|16@1+ (1,-20000) [-20000|45535] "A"  PC,SBMU
 SG_ M2P_SOH_04 : 32|10@1+ (0.1,0) [0|102.3] "%"  PC,SBMU
 SG_ M2P_RSOC_04 : 42|10@1+ (0.1,0) [0|102.3] "%"  PC,SBMU
 SG_ M2P_DSOC_04 : 52|10@1+ (0.1,0) [0|102.3] "%"  PC,SBMU
 SG_ CMD_of_Closed_Loop_04 : 62|1@1+ (1,0) [0|1] ""  PC,SBMU
 SG_ SOCDiffHighFlg : 63|1@1+ (1,0) [0|1] ""  PC,SBMU

BO_ 2332159637 M2P_SUMDATA1__05: 8 MBMU
 SG_ M2P_Measure_Vol_05 : 0|16@1+ (0.1,0) [0|6553.5] "V"  PC,SBMU
 SG_ M2P_Current_05 : 16|16@1+ (1,-20000) [-20000|45535] "A"  PC,SBMU
 SG_ M2P_SOH_05 : 32|10@1+ (0.1,0) [0|102.3] "%"  PC,SBMU
 SG_ M2P_RSOC_05 : 42|10@1+ (0.1,0) [0|102.3] "%"  PC,SBMU
 SG_ M2P_DSOC_05 : 52|10@1+ (0.1,0) [0|102.3] "%"  PC,SBMU
 SG_ CMD_of_Closed_Loop_05 : 62|1@1+ (1,0) [0|1] ""  PC,SBMU
 SG_ SOCDiffHighFlg : 63|1@1+ (1,0) [0|1] ""  PC,SBMU

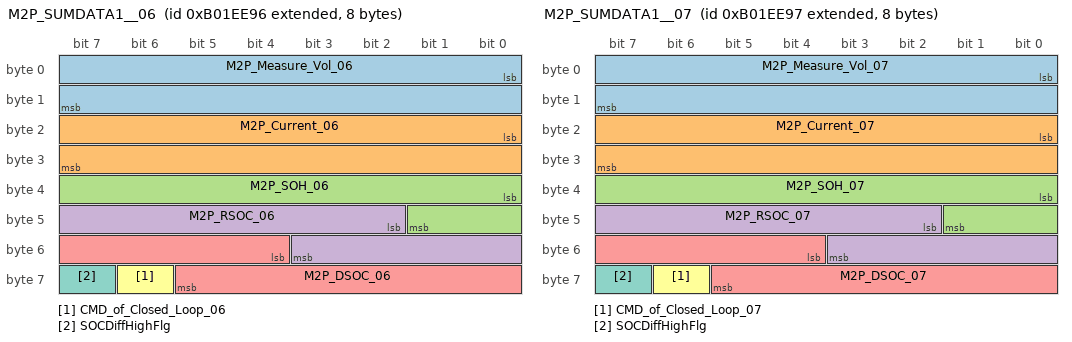
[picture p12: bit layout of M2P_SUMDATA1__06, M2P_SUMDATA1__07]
BO_ 2332159638 M2P_SUMDATA1__06: 8 MBMU
 SG_ M2P_Measure_Vol_06 : 0|16@1+ (0.1,0) [0|6553.5] "V"  PC,SBMU
 SG_ M2P_Current_06 : 16|16@1+ (1,-20000) [-20000|45535] "A"  PC,SBMU
 SG_ M2P_SOH_06 : 32|10@1+ (0.1,0) [0|102.3] "%"  PC,SBMU
 SG_ M2P_RSOC_06 : 42|10@1+ (0.1,0) [0|102.3] "%"  PC,SBMU
 SG_ M2P_DSOC_06 : 52|10@1+ (0.1,0) [0|102.3] "%"  PC,SBMU
 SG_ CMD_of_Closed_Loop_06 : 62|1@1+ (1,0) [0|1] ""  PC,SBMU
 SG_ SOCDiffHighFlg : 63|1@1+ (1,0) [0|1] ""  PC,SBMU

BO_ 2332159639 M2P_SUMDATA1__07: 8 MBMU
 SG_ M2P_Measure_Vol_07 : 0|16@1+ (0.1,0) [0|6553.5] "V"  PC,SBMU
 SG_ M2P_Current_07 : 16|16@1+ (1,-20000) [-20000|45535] "A"  PC,SBMU
 SG_ M2P_SOH_07 : 32|10@1+ (0.1,0) [0|102.3] "%"  PC,SBMU
 SG_ M2P_RSOC_07 : 42|10@1+ (0.1,0) [0|102.3] "%"  PC,SBMU
 SG_ M2P_DSOC_07 : 52|10@1+ (0.1,0) [0|102.3] "%"  PC,SBMU
 SG_ CMD_of_Closed_Loop_07 : 62|1@1+ (1,0) [0|1] ""  PC,SBMU
 SG_ SOCDiffHighFlg : 63|1@1+ (1,0) [0|1] ""  PC,SBMU

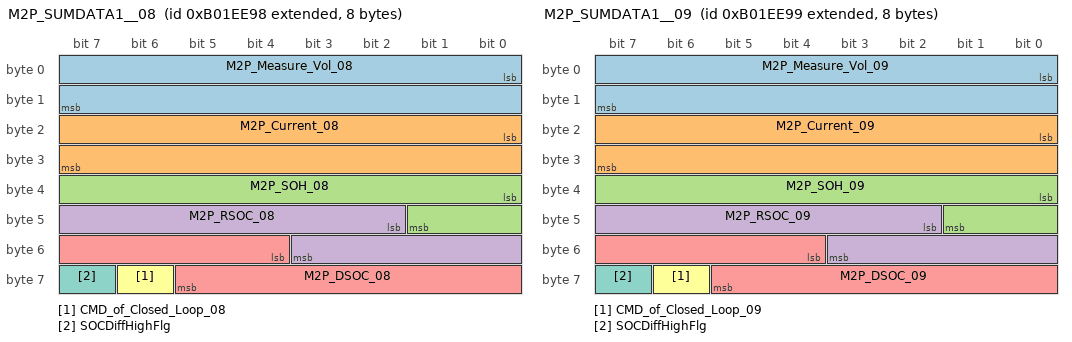
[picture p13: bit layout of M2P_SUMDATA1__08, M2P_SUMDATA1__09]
BO_ 2332159640 M2P_SUMDATA1__08: 8 MBMU
 SG_ M2P_Measure_Vol_08 : 0|16@1+ (0.1,0) [0|6553.5] "V"  PC,SBMU
 SG_ M2P_Current_08 : 16|16@1+ (1,-20000) [-20000|45535] "A"  PC,SBMU
 SG_ M2P_SOH_08 : 32|10@1+ (0.1,0) [0|102.3] "%"  PC,SBMU
 SG_ M2P_RSOC_08 : 42|10@1+ (0.1,0) [0|102.3] "%"  PC,SBMU
 SG_ M2P_DSOC_08 : 52|10@1+ (0.1,0) [0|102.3] "%"  PC,SBMU
 SG_ CMD_of_Closed_Loop_08 : 62|1@1+ (1,0) [0|1] ""  PC,SBMU
 SG_ SOCDiffHighFlg : 63|1@1+ (1,0) [0|1] ""  PC,SBMU

BO_ 2332159641 M2P_SUMDATA1__09: 8 MBMU
 SG_ M2P_Measure_Vol_09 : 0|16@1+ (0.1,0) [0|6553.5] "V"  PC,SBMU
 SG_ M2P_Current_09 : 16|16@1+ (1,-20000) [-20000|45535] "A"  PC,SBMU
 SG_ M2P_SOH_09 : 32|10@1+ (0.1,0) [0|102.3] "%"  PC,SBMU
 SG_ M2P_RSOC_09 : 42|10@1+ (0.1,0) [0|102.3] "%"  PC,SBMU
 SG_ M2P_DSOC_09 : 52|10@1+ (0.1,0) [0|102.3] "%"  PC,SBMU
 SG_ CMD_of_Closed_Loop_09 : 62|1@1+ (1,0) [0|1] ""  PC,SBMU
 SG_ SOCDiffHighFlg : 63|1@1+ (1,0) [0|1] ""  PC,SBMU

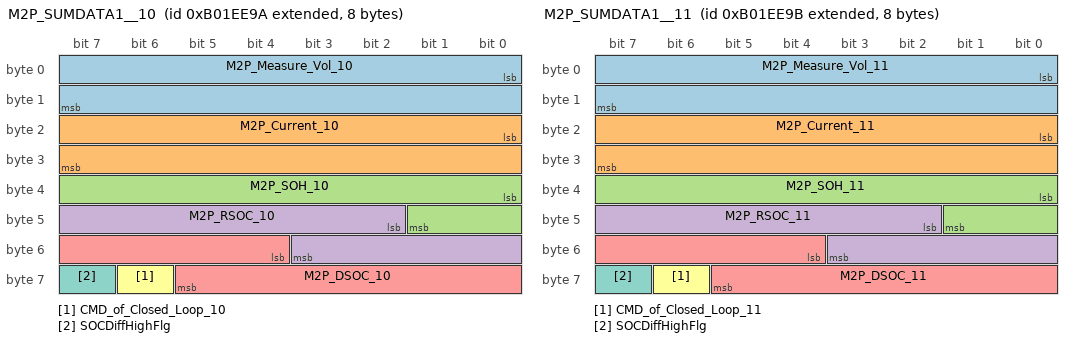
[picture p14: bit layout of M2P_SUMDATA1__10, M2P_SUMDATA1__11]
BO_ 2332159642 M2P_SUMDATA1__10: 8 MBMU
 SG_ M2P_Measure_Vol_10 : 0|16@1+ (0.1,0) [0|6553.5] "V"  PC,SBMU
 SG_ M2P_Current_10 : 16|16@1+ (1,-20000) [-20000|45535] "A"  PC,SBMU
 SG_ M2P_SOH_10 : 32|10@1+ (0.1,0) [0|102.3] "%"  PC,SBMU
 SG_ M2P_RSOC_10 : 42|10@1+ (0.1,0) [0|102.3] "%"  PC,SBMU
 SG_ M2P_DSOC_10 : 52|10@1+ (0.1,0) [0|102.3] "%"  PC,SBMU
 SG_ CMD_of_Closed_Loop_10 : 62|1@1+ (1,0) [0|1] ""  PC,SBMU
 SG_ SOCDiffHighFlg : 63|1@1+ (1,0) [0|1] ""  PC,SBMU

BO_ 2332159643 M2P_SUMDATA1__11: 8 MBMU
 SG_ M2P_Measure_Vol_11 : 0|16@1+ (0.1,0) [0|6553.5] "V"  PC,SBMU
 SG_ M2P_Current_11 : 16|16@1+ (1,-20000) [-20000|45535] "A"  PC,SBMU
 SG_ M2P_SOH_11 : 32|10@1+ (0.1,0) [0|102.3] "%"  PC,SBMU
 SG_ M2P_RSOC_11 : 42|10@1+ (0.1,0) [0|102.3] "%"  PC,SBMU
 SG_ M2P_DSOC_11 : 52|10@1+ (0.1,0) [0|102.3] "%"  PC,SBMU
 SG_ CMD_of_Closed_Loop_11 : 62|1@1+ (1,0) [0|1] ""  PC,SBMU
 SG_ SOCDiffHighFlg : 63|1@1+ (1,0) [0|1] ""  PC,SBMU

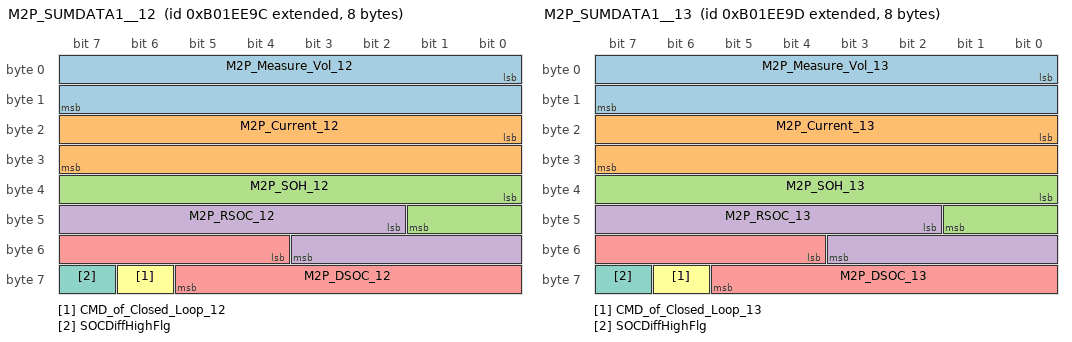
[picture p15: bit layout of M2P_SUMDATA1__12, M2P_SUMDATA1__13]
BO_ 2332159644 M2P_SUMDATA1__12: 8 MBMU
 SG_ M2P_Measure_Vol_12 : 0|16@1+ (0.1,0) [0|6553.5] "V"  PC,SBMU
 SG_ M2P_Current_12 : 16|16@1+ (1,-20000) [-20000|45535] "A"  PC,SBMU
 SG_ M2P_SOH_12 : 32|10@1+ (0.1,0) [0|102.3] "%"  PC,SBMU
 SG_ M2P_RSOC_12 : 42|10@1+ (0.1,0) [0|102.3] "%"  PC,SBMU
 SG_ M2P_DSOC_12 : 52|10@1+ (0.1,0) [0|102.3] "%"  PC,SBMU
 SG_ CMD_of_Closed_Loop_12 : 62|1@1+ (1,0) [0|1] ""  PC,SBMU
 SG_ SOCDiffHighFlg : 63|1@1+ (1,0) [0|1] ""  PC,SBMU

BO_ 2332159645 M2P_SUMDATA1__13: 8 MBMU
 SG_ M2P_Measure_Vol_13 : 0|16@1+ (0.1,0) [0|6553.5] "V"  PC,SBMU
 SG_ M2P_Current_13 : 16|16@1+ (1,-20000) [-20000|45535] "A"  PC,SBMU
 SG_ M2P_SOH_13 : 32|10@1+ (0.1,0) [0|102.3] "%"  PC,SBMU
 SG_ M2P_RSOC_13 : 42|10@1+ (0.1,0) [0|102.3] "%"  PC,SBMU
 SG_ M2P_DSOC_13 : 52|10@1+ (0.1,0) [0|102.3] "%"  PC,SBMU
 SG_ CMD_of_Closed_Loop_13 : 62|1@1+ (1,0) [0|1] ""  PC,SBMU
 SG_ SOCDiffHighFlg : 63|1@1+ (1,0) [0|1] ""  PC,SBMU

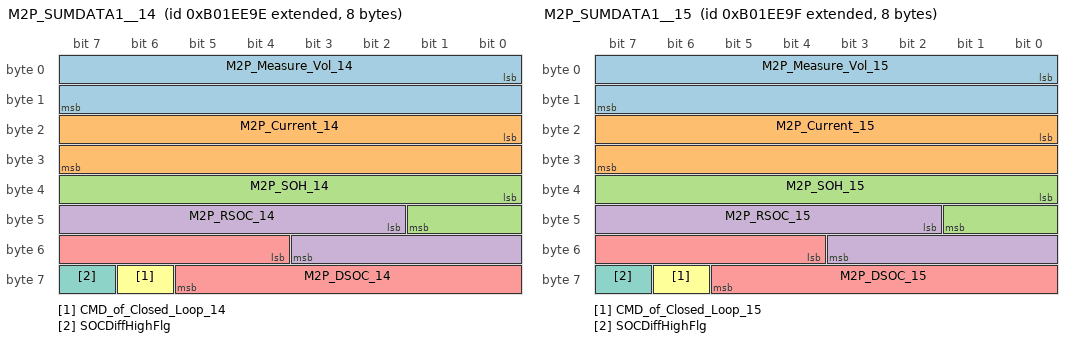
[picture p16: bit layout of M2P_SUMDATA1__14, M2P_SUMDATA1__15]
BO_ 2332159646 M2P_SUMDATA1__14: 8 MBMU
 SG_ M2P_Measure_Vol_14 : 0|16@1+ (0.1,0) [0|6553.5] "V"  PC,SBMU
 SG_ M2P_Current_14 : 16|16@1+ (1,-20000) [-20000|45535] "A"  PC,SBMU
 SG_ M2P_SOH_14 : 32|10@1+ (0.1,0) [0|102.3] "%"  PC,SBMU
 SG_ M2P_RSOC_14 : 42|10@1+ (0.1,0) [0|102.3] "%"  PC,SBMU
 SG_ M2P_DSOC_14 : 52|10@1+ (0.1,0) [0|102.3] "%"  PC,SBMU
 SG_ CMD_of_Closed_Loop_14 : 62|1@1+ (1,0) [0|1] ""  PC,SBMU
 SG_ SOCDiffHighFlg : 63|1@1+ (1,0) [0|1] ""  PC,SBMU

BO_ 2332159647 M2P_SUMDATA1__15: 8 MBMU
 SG_ M2P_Measure_Vol_15 : 0|16@1+ (0.1,0) [0|6553.5] "V"  PC,SBMU
 SG_ M2P_Current_15 : 16|16@1+ (1,-20000) [-20000|45535] "A"  PC,SBMU
 SG_ M2P_SOH_15 : 32|10@1+ (0.1,0) [0|102.3] "%"  PC,SBMU
 SG_ M2P_RSOC_15 : 42|10@1+ (0.1,0) [0|102.3] "%"  PC,SBMU
 SG_ M2P_DSOC_15 : 52|10@1+ (0.1,0) [0|102.3] "%"  PC,SBMU
 SG_ CMD_of_Closed_Loop_15 : 62|1@1+ (1,0) [0|1] ""  PC,SBMU
 SG_ SOCDiffHighFlg : 63|1@1+ (1,0) [0|1] ""  PC,SBMU

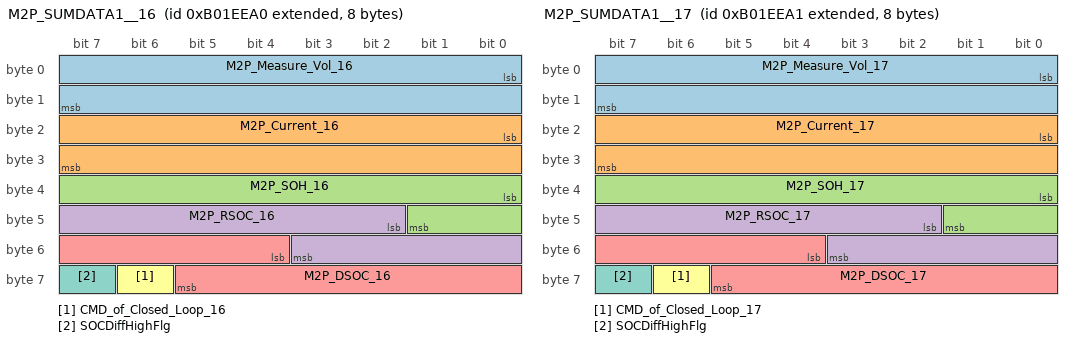
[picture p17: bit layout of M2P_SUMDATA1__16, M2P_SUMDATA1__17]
BO_ 2332159648 M2P_SUMDATA1__16: 8 MBMU
 SG_ M2P_Measure_Vol_16 : 0|16@1+ (0.1,0) [0|6553.5] "V"  PC,SBMU
 SG_ M2P_Current_16 : 16|16@1+ (1,-20000) [-20000|45535] "A"  PC,SBMU
 SG_ M2P_SOH_16 : 32|10@1+ (0.1,0) [0|102.3] "%"  PC,SBMU
 SG_ M2P_RSOC_16 : 42|10@1+ (0.1,0) [0|102.3] "%"  PC,SBMU
 SG_ M2P_DSOC_16 : 52|10@1+ (0.1,0) [0|102.3] "%"  PC,SBMU
 SG_ CMD_of_Closed_Loop_16 : 62|1@1+ (1,0) [0|1] ""  PC,SBMU
 SG_ SOCDiffHighFlg : 63|1@1+ (1,0) [0|1] ""  PC,SBMU

BO_ 2332159649 M2P_SUMDATA1__17: 8 MBMU
 SG_ M2P_Measure_Vol_17 : 0|16@1+ (0.1,0) [0|6553.5] "V"  PC,SBMU
 SG_ M2P_Current_17 : 16|16@1+ (1,-20000) [-20000|45535] "A"  PC,SBMU
 SG_ M2P_SOH_17 : 32|10@1+ (0.1,0) [0|102.3] "%"  PC,SBMU
 SG_ M2P_RSOC_17 : 42|10@1+ (0.1,0) [0|102.3] "%"  PC,SBMU
 SG_ M2P_DSOC_17 : 52|10@1+ (0.1,0) [0|102.3] "%"  PC,SBMU
 SG_ CMD_of_Closed_Loop_17 : 62|1@1+ (1,0) [0|1] ""  PC,SBMU
 SG_ SOCDiffHighFlg : 63|1@1+ (1,0) [0|1] ""  PC,SBMU

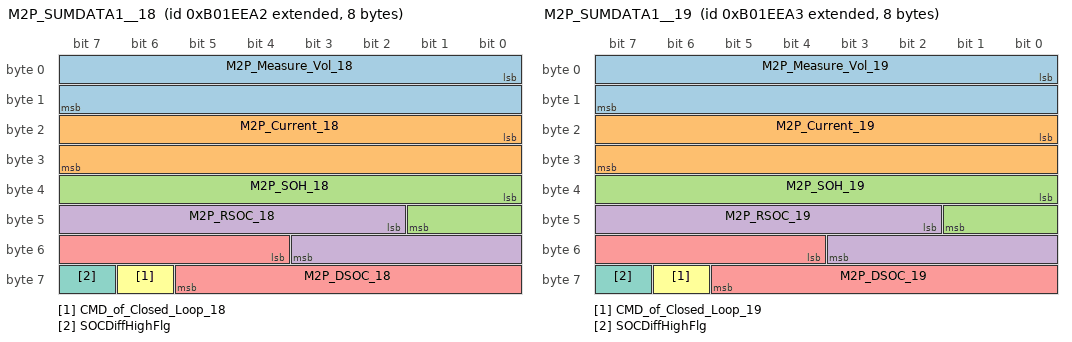
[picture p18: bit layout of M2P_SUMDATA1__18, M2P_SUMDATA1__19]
BO_ 2332159650 M2P_SUMDATA1__18: 8 MBMU
 SG_ M2P_Measure_Vol_18 : 0|16@1+ (0.1,0) [0|6553.5] "V"  PC,SBMU
 SG_ M2P_Current_18 : 16|16@1+ (1,-20000) [-20000|45535] "A"  PC,SBMU
 SG_ M2P_SOH_18 : 32|10@1+ (0.1,0) [0|102.3] "%"  PC,SBMU
 SG_ M2P_RSOC_18 : 42|10@1+ (0.1,0) [0|102.3] "%"  PC,SBMU
 SG_ M2P_DSOC_18 : 52|10@1+ (0.1,0) [0|102.3] "%"  PC,SBMU
 SG_ CMD_of_Closed_Loop_18 : 62|1@1+ (1,0) [0|1] ""  PC,SBMU
 SG_ SOCDiffHighFlg : 63|1@1+ (1,0) [0|1] ""  PC,SBMU

BO_ 2332159651 M2P_SUMDATA1__19: 8 MBMU
 SG_ M2P_Measure_Vol_19 : 0|16@1+ (0.1,0) [0|6553.5] "V"  PC,SBMU
 SG_ M2P_Current_19 : 16|16@1+ (1,-20000) [-20000|45535] "A"  PC,SBMU
 SG_ M2P_SOH_19 : 32|10@1+ (0.1,0) [0|102.3] "%"  PC,SBMU
 SG_ M2P_RSOC_19 : 42|10@1+ (0.1,0) [0|102.3] "%"  PC,SBMU
 SG_ M2P_DSOC_19 : 52|10@1+ (0.1,0) [0|102.3] "%"  PC,SBMU
 SG_ CMD_of_Closed_Loop_19 : 62|1@1+ (1,0) [0|1] ""  PC,SBMU
 SG_ SOCDiffHighFlg : 63|1@1+ (1,0) [0|1] ""  PC,SBMU

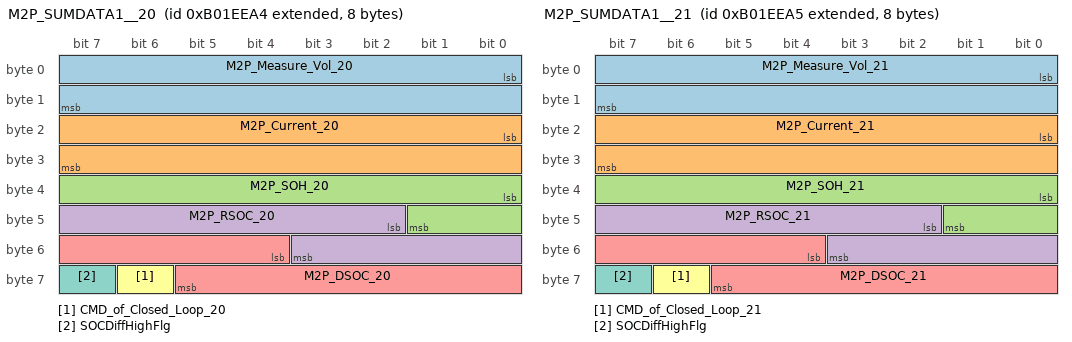
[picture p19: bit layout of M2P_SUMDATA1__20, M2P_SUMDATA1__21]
BO_ 2332159652 M2P_SUMDATA1__20: 8 MBMU
 SG_ M2P_Measure_Vol_20 : 0|16@1+ (0.1,0) [0|6553.5] "V"  PC,SBMU
 SG_ M2P_Current_20 : 16|16@1+ (1,-20000) [-20000|45535] "A"  PC,SBMU
 SG_ M2P_SOH_20 : 32|10@1+ (0.1,0) [0|102.3] "%"  PC,SBMU
 SG_ M2P_RSOC_20 : 42|10@1+ (0.1,0) [0|102.3] "%"  PC,SBMU
 SG_ M2P_DSOC_20 : 52|10@1+ (0.1,0) [0|102.3] "%"  PC,SBMU
 SG_ CMD_of_Closed_Loop_20 : 62|1@1+ (1,0) [0|1] ""  PC,SBMU
 SG_ SOCDiffHighFlg : 63|1@1+ (1,0) [0|1] ""  PC,SBMU

BO_ 2332159653 M2P_SUMDATA1__21: 8 MBMU
 SG_ M2P_Measure_Vol_21 : 0|16@1+ (0.1,0) [0|6553.5] "V"  PC,SBMU
 SG_ M2P_Current_21 : 16|16@1+ (1,-20000) [-20000|45535] "A"  PC,SBMU
 SG_ M2P_SOH_21 : 32|10@1+ (0.1,0) [0|102.3] "%"  PC,SBMU
 SG_ M2P_RSOC_21 : 42|10@1+ (0.1,0) [0|102.3] "%"  PC,SBMU
 SG_ M2P_DSOC_21 : 52|10@1+ (0.1,0) [0|102.3] "%"  PC,SBMU
 SG_ CMD_of_Closed_Loop_21 : 62|1@1+ (1,0) [0|1] ""  PC,SBMU
 SG_ SOCDiffHighFlg : 63|1@1+ (1,0) [0|1] ""  PC,SBMU

BO_ 2332159654 M2P_SUMDATA1__22: 8 MBMU
 SG_ M2P_Measure_Vol_22 : 0|16@1+ (0.1,0) [0|6553.5] "V"  PC,SBMU
 SG_ M2P_Current_22 : 16|16@1+ (1,-20000) [-20000|45535] "A"  PC,SBMU
 SG_ M2P_SOH_22 : 32|10@1+ (0.1,0) [0|102.3] "%"  PC,SBMU
 SG_ M2P_RSOC_22 : 42|10@1+ (0.1,0) [0|102.3] "%"  PC,SBMU
 SG_ M2P_DSOC_22 : 52|10@1+ (0.1,0) [0|102.3] "%"  PC,SBMU
 SG_ CMD_of_Closed_Loop_22 : 62|1@1+ (1,0) [0|1] ""  PC,SBMU
 SG_ SOCDiffHighFlg : 63|1@1+ (1,0) [0|1] ""  PC,SBMU

BO_ 2332159655 M2P_SUMDATA1__23: 8 MBMU
 SG_ M2P_Measure_Vol_23 : 0|16@1+ (0.1,0) [0|6553.5] "V"  PC,SBMU
 SG_ M2P_Current_23 : 16|16@1+ (1,-20000) [-20000|45535] "A"  PC,SBMU
 SG_ M2P_SOH_23 : 32|10@1+ (0.1,0) [0|102.3] "%"  PC,SBMU
 SG_ M2P_RSOC_23 : 42|10@1+ (0.1,0) [0|102.3] "%"  PC,SBMU
 SG_ M2P_DSOC_23 : 52|10@1+ (0.1,0) [0|102.3] "%"  PC,SBMU
 SG_ CMD_of_Closed_Loop_23 : 62|1@1+ (1,0) [0|1] ""  PC,SBMU
 SG_ SOCDiffHighFlg : 63|1@1+ (1,0) [0|1] ""  PC,SBMU

BO_ 2332159656 M2P_SUMDATA1__24: 8 MBMU
 SG_ M2P_Measure_Vol_24 : 0|16@1+ (0.1,0) [0|6553.5] "V"  PC,SBMU
 SG_ M2P_Current_24 : 16|16@1+ (1,-20000) [-20000|45535] "A"  PC,SBMU
 SG_ M2P_SOH_24 : 32|10@1+ (0.1,0) [0|102.3] "%"  PC,SBMU
 SG_ M2P_RSOC_24 : 42|10@1+ (0.1,0) [0|102.3] "%"  PC,SBMU
 SG_ M2P_DSOC_24 : 52|10@1+ (0.1,0) [0|102.3] "%"  PC,SBMU
 SG_ CMD_of_Closed_Loop_24 : 62|1@1+ (1,0) [0|1] ""  PC,SBMU
 SG_ SOCDiffHighFlg : 63|1@1+ (1,0) [0|1] ""  PC,SBMU

BO_ 2332159657 M2P_SUMDATA1__25: 8 MBMU
 SG_ M2P_Measure_Vol_25 : 0|16@1+ (0.1,0) [0|6553.5] "V"  PC,SBMU
 SG_ M2P_Current_25 : 16|16@1+ (1,-20000) [-20000|45535] "A"  PC,SBMU
 SG_ M2P_SOH_25 : 32|10@1+ (0.1,0) [0|102.3] "%"  PC,SBMU
 SG_ M2P_RSOC_25 : 42|10@1+ (0.1,0) [0|102.3] "%"  PC,SBMU
 SG_ M2P_DSOC_25 : 52|10@1+ (0.1,0) [0|102.3] "%"  PC,SBMU
 SG_ CMD_of_Closed_Loop_25 : 62|1@1+ (1,0) [0|1] ""  PC,SBMU
 SG_ SOCDiffHighFlg : 63|1@1+ (1,0) [0|1] ""  PC,SBMU

BO_ 2332159658 M2P_SUMDATA1__26: 8 MBMU
 SG_ M2P_Measure_Vol_26 : 0|16@1+ (0.1,0) [0|6553.5] "V"  PC,SBMU
 SG_ M2P_Current_26 : 16|16@1+ (1,-20000) [-20000|45535] "A"  PC,SBMU
 SG_ M2P_SOH_26 : 32|10@1+ (0.1,0) [0|102.3] "%"  PC,SBMU
 SG_ M2P_RSOC_26 : 42|10@1+ (0.1,0) [0|102.3] "%"  PC,SBMU
 SG_ M2P_DSOC_26 : 52|10@1+ (0.1,0) [0|102.3] "%"  PC,SBMU
 SG_ CMD_of_Closed_Loop_26 : 62|1@1+ (1,0) [0|1] ""  PC,SBMU
 SG_ SOCDiffHighFlg : 63|1@1+ (1,0) [0|1] ""  PC,SBMU

BO_ 2332159659 M2P_SUMDATA1__27: 8 MBMU
 SG_ M2P_Measure_Vol_27 : 0|16@1+ (0.1,0) [0|6553.5] "V"  PC,SBMU
 SG_ M2P_Current_27 : 16|16@1+ (1,-20000) [-20000|45535] "A"  PC,SBMU
 SG_ M2P_SOH_27 : 32|10@1+ (0.1,0) [0|102.3] "%"  PC,SBMU
 SG_ M2P_RSOC_27 : 42|10@1+ (0.1,0) [0|102.3] "%"  PC,SBMU
 SG_ M2P_DSOC_27 : 52|10@1+ (0.1,0) [0|102.3] "%"  PC,SBMU
 SG_ CMD_of_Closed_Loop_27 : 62|1@1+ (1,0) [0|1] ""  PC,SBMU
 SG_ SOCDiffHighFlg : 63|1@1+ (1,0) [0|1] ""  PC,SBMU

BO_ 2332159660 M2P_SUMDATA1__28: 8 MBMU
 SG_ M2P_Measure_Vol_28 : 0|16@1+ (0.1,0) [0|6553.5] "V"  PC,SBMU
 SG_ M2P_Current_28 : 16|16@1+ (1,-20000) [-20000|45535] "A"  PC,SBMU
 SG_ M2P_SOH_28 : 32|10@1+ (0.1,0) [0|102.3] "%"  PC,SBMU
 SG_ M2P_RSOC_28 : 42|10@1+ (0.1,0) [0|102.3] "%"  PC,SBMU
 SG_ M2P_DSOC_28 : 52|10@1+ (0.1,0) [0|102.3] "%"  PC,SBMU
 SG_ CMD_of_Closed_Loop_28 : 62|1@1+ (1,0) [0|1] ""  PC,SBMU
 SG_ SOCDiffHighFlg : 63|1@1+ (1,0) [0|1] ""  PC,SBMU

BO_ 2332159661 M2P_SUMDATA1__29: 8 MBMU
 SG_ M2P_Measure_Vol_29 : 0|16@1+ (0.1,0) [0|6553.5] "V"  PC,SBMU
 SG_ M2P_Current_29 : 16|16@1+ (1,-20000) [-20000|45535] "A"  PC,SBMU
 SG_ M2P_SOH_29 : 32|10@1+ (0.1,0) [0|102.3] "%"  PC,SBMU
 SG_ M2P_RSOC_29 : 42|10@1+ (0.1,0) [0|102.3] "%"  PC,SBMU
 SG_ M2P_DSOC_29 : 52|10@1+ (0.1,0) [0|102.3] "%"  PC,SBMU
 SG_ CMD_of_Closed_Loop_29 : 62|1@1+ (1,0) [0|1] ""  PC,SBMU
 SG_ SOCDiffHighFlg : 63|1@1+ (1,0) [0|1] ""  PC,SBMU

BO_ 2332159662 M2P_SUMDATA1__30: 8 MBMU
 SG_ M2P_Measure_Vol_30 : 0|16@1+ (0.1,0) [0|6553.5] "V"  PC,SBMU
 SG_ M2P_Current_30 : 16|16@1+ (1,-20000) [-20000|45535] "A"  PC,SBMU
 SG_ M2P_SOH_30 : 32|10@1+ (0.1,0) [0|102.3] "%"  PC,SBMU
 SG_ M2P_RSOC_30 : 42|10@1+ (0.1,0) [0|102.3] "%"  PC,SBMU
 SG_ M2P_DSOC_30 : 52|10@1+ (0.1,0) [0|102.3] "%"  PC,SBMU
 SG_ CMD_of_Closed_Loop_30 : 62|1@1+ (1,0) [0|1] ""  PC,SBMU
 SG_ SOCDiffHighFlg : 63|1@1+ (1,0) [0|1] ""  PC,SBMU

BO_ 2332159663 M2P_SUMDATA1__31: 8 MBMU
 SG_ M2P_Measure_Vol_31 : 0|16@1+ (0.1,0) [0|6553.5] "V"  PC,SBMU
 SG_ M2P_Current_31 : 16|16@1+ (1,-20000) [-20000|45535] "A"  PC,SBMU
 SG_ M2P_SOH_31 : 32|10@1+ (0.1,0) [0|102.3] "%"  PC,SBMU
 SG_ M2P_RSOC_31 : 42|10@1+ (0.1,0) [0|102.3] "%"  PC,SBMU
 SG_ M2P_DSOC_31 : 52|10@1+ (0.1,0) [0|102.3] "%"  PC,SBMU
 SG_ CMD_of_Closed_Loop_31 : 62|1@1+ (1,0) [0|1] ""  PC,SBMU
 SG_ SOCDiffHighFlg : 63|1@1+ (1,0) [0|1] ""  PC,SBMU

BO_ 2332225169 M2P_SUMDATA2__01: 8 MBMU
 SG_ M2P_LifeSignal_01 : 0|4@1+ (1,0) [0|15] ""  PC,SBMU
 SG_ M2P_ST_Power_01 : 4|1@1+ (1,0) [0|1] ""  PC,SBMU
 SG_ M2P_ST_Master_slave_01 : 5|1@1+ (1,0) [0|1] ""  PC,SBMU
 SG_ M2P_Status_Fan_SW_01 : 7|1@1+ (1,0) [0|1] ""  PC,SBMU
 SG_ M2P_Circuit_Breaker_01 : 8|16@1+ (1,0) [0|65535] ""  PC,SBMU
 SG_ M2P_NUM_OF_SlaveMBMU : 24|4@1+ (1,0) [0|15] ""  PC,SBMU
 SG_ M2P_RackInhabitResult : 28|2@1+ (1,0) [0|3] ""  PC,SBMU
 SG_ M2P_STofSBMUAutoCoding_01 : 30|2@1+ (1,0) [0|3] ""  PC,SBMU
 SG_ M2P_LvSelfLock : 32|1@1+ (1,0) [0|1] ""  PC,SBMU
 SG_ M2P_SbmuPwrOnFlg : 33|1@1+ (1,0) [0|1] ""  PC,SBMU
 SG_ M2P_InsulPwrOnFlg : 34|1@1+ (1,0) [0|1] ""  PC,SBMU
 SG_ M2P_HvOffReqFlg : 35|1@1+ (1,0) [0|1] ""  PC,SBMU
 SG_ M2P_HvOnAllowFlg : 36|1@1+ (1,0) [0|1] ""  PC,SBMU
 SG_ M2P_SBMULvoffAbnomal : 37|1@1+ (1,0) [0|1] ""  PC,SBMU
 SG_ M2P_LVPwrDFaultR : 38|2@1+ (1,0) [0|3] ""  PC,SBMU
 SG_ M2P_SysRunState : 40|3@1+ (1,0) [0|7] ""  PC,SBMU
 SG_ M2P_MIN_NUM_OF_ONLINE_SBMU : 43|5@1+ (1,0) [0|31] ""  PC,SBMU
 SG_ MBMU_Tank_Num_RelayOn : 48|8@1+ (1,0) [0|255] ""  PC,SBMU
 SG_ M2P_NUM_OF_SBMU : 56|8@1+ (1,0) [0|255] ""  PC

BO_ 2332225170 M2P_SUMDATA2__02: 8 MBMU
 SG_ M2P_LifeSignal_02 : 0|4@1+ (1,0) [0|15] ""  PC,SBMU
 SG_ M2P_ST_Power_02 : 4|1@1+ (1,0) [0|1] ""  PC,SBMU
 SG_ M2P_ST_Master_slave_02 : 5|1@1+ (1,0) [0|1] ""  PC,SBMU
 SG_ M2P_Status_Fan_SW_02 : 7|1@1+ (1,0) [0|1] ""  PC,SBMU
 SG_ M2P_Circuit_Breaker_02 : 8|16@1+ (1,0) [0|65535] ""  PC,SBMU
 SG_ M2P_NUM_OF_SlaveMBMU : 24|4@1+ (1,0) [0|15] ""  PC,SBMU
 SG_ M2P_RackInhabitResult : 28|2@1+ (1,0) [0|3] ""  PC,SBMU
 SG_ M2P_STofSBMUAutoCoding_02 : 30|2@1+ (1,0) [0|3] ""  PC,SBMU
 SG_ M2P_LvSelfLock : 32|1@1+ (1,0) [0|1] ""  PC,SBMU
 SG_ M2P_SbmuPwrOnFlg : 33|1@1+ (1,0) [0|1] ""  PC,SBMU
 SG_ M2P_InsulPwrOnFlg : 34|1@1+ (1,0) [0|1] ""  PC,SBMU
 SG_ M2P_HvOffReqFlg : 35|1@1+ (1,0) [0|1] ""  PC,SBMU
 SG_ M2P_HvOnAllowFlg : 36|1@1+ (1,0) [0|1] ""  PC,SBMU
 SG_ M2P_SBMULvoffAbnomal : 37|1@1+ (1,0) [0|1] ""  PC,SBMU
 SG_ M2P_LVPwrDFaultR : 38|2@1+ (1,0) [0|3] ""  PC,SBMU
 SG_ M2P_SysRunState : 40|3@1+ (1,0) [0|7] ""  PC,SBMU
 SG_ M2P_MIN_NUM_OF_ONLINE_SBMU : 43|5@1+ (1,0) [0|31] ""  PC,SBMU
 SG_ MBMU_Tank_Num_RelayOn : 48|8@1+ (1,0) [0|255] ""  PC,SBMU
 SG_ M2P_NUM_OF_SBMU : 56|8@1+ (1,0) [0|255] ""  PC

BO_ 2332225171 M2P_SUMDATA2__03: 8 MBMU
 SG_ M2P_LifeSignal_03 : 0|4@1+ (1,0) [0|15] ""  PC,SBMU
 SG_ M2P_ST_Power_03 : 4|1@1+ (1,0) [0|1] ""  PC,SBMU
 SG_ M2P_ST_Master_slave_03 : 5|1@1+ (1,0) [0|1] ""  PC,SBMU
 SG_ M2P_Status_Fan_SW_03 : 7|1@1+ (1,0) [0|1] ""  PC,SBMU
 SG_ M2P_Circuit_Breaker_03 : 8|16@1+ (1,0) [0|65535] ""  PC,SBMU
 SG_ M2P_NUM_OF_SlaveMBMU : 24|4@1+ (1,0) [0|15] ""  PC,SBMU
 SG_ M2P_RackInhabitResult : 28|2@1+ (1,0) [0|3] ""  PC,SBMU
 SG_ M2P_STofSBMUAutoCoding_03 : 30|2@1+ (1,0) [0|3] ""  PC,SBMU
 SG_ M2P_LvSelfLock : 32|1@1+ (1,0) [0|1] ""  PC,SBMU
 SG_ M2P_SbmuPwrOnFlg : 33|1@1+ (1,0) [0|1] ""  PC,SBMU
 SG_ M2P_InsulPwrOnFlg : 34|1@1+ (1,0) [0|1] ""  PC,SBMU
 SG_ M2P_HvOffReqFlg : 35|1@1+ (1,0) [0|1] ""  PC,SBMU
 SG_ M2P_HvOnAllowFlg : 36|1@1+ (1,0) [0|1] ""  PC,SBMU
 SG_ M2P_SBMULvoffAbnomal : 37|1@1+ (1,0) [0|1] ""  PC,SBMU
 SG_ M2P_LVPwrDFaultR : 38|2@1+ (1,0) [0|3] ""  PC,SBMU
 SG_ M2P_SysRunState : 40|3@1+ (1,0) [0|7] ""  PC,SBMU
 SG_ M2P_MIN_NUM_OF_ONLINE_SBMU : 43|5@1+ (1,0) [0|31] ""  PC,SBMU
 SG_ MBMU_Tank_Num_RelayOn : 48|8@1+ (1,0) [0|255] ""  PC,SBMU
 SG_ M2P_NUM_OF_SBMU : 56|8@1+ (1,0) [0|255] ""  PC

BO_ 2332225172 M2P_SUMDATA2__04: 8 MBMU
 SG_ M2P_LifeSignal_04 : 0|4@1+ (1,0) [0|15] ""  PC,SBMU
 SG_ M2P_ST_Power_04 : 4|1@1+ (1,0) [0|1] ""  PC,SBMU
 SG_ M2P_ST_Master_slave_04 : 5|1@1+ (1,0) [0|1] ""  PC,SBMU
 SG_ M2P_Status_Fan_SW_04 : 7|1@1+ (1,0) [0|1] ""  PC,SBMU
 SG_ M2P_Circuit_Breaker_04 : 8|16@1+ (1,0) [0|65535] ""  PC,SBMU
 SG_ M2P_NUM_OF_SlaveMBMU : 24|4@1+ (1,0) [0|15] ""  PC,SBMU
 SG_ M2P_RackInhabitResult : 28|2@1+ (1,0) [0|3] ""  PC,SBMU
 SG_ M2P_STofSBMUAutoCoding_04 : 30|2@1+ (1,0) [0|3] ""  PC,SBMU
 SG_ M2P_LvSelfLock : 32|1@1+ (1,0) [0|1] ""  PC,SBMU
 SG_ M2P_SbmuPwrOnFlg : 33|1@1+ (1,0) [0|1] ""  PC,SBMU
 SG_ M2P_InsulPwrOnFlg : 34|1@1+ (1,0) [0|1] ""  PC,SBMU
 SG_ M2P_HvOffReqFlg : 35|1@1+ (1,0) [0|1] ""  PC,SBMU
 SG_ M2P_HvOnAllowFlg : 36|1@1+ (1,0) [0|1] ""  PC,SBMU
 SG_ M2P_SBMULvoffAbnomal : 37|1@1+ (1,0) [0|1] ""  PC,SBMU
 SG_ M2P_LVPwrDFaultR : 38|2@1+ (1,0) [0|3] ""  PC,SBMU
 SG_ M2P_SysRunState : 40|3@1+ (1,0) [0|7] ""  PC,SBMU
 SG_ M2P_MIN_NUM_OF_ONLINE_SBMU : 43|5@1+ (1,0) [0|31] ""  PC,SBMU
 SG_ MBMU_Tank_Num_RelayOn : 48|8@1+ (1,0) [0|255] ""  PC,SBMU
 SG_ M2P_NUM_OF_SBMU : 56|8@1+ (1,0) [0|255] ""  PC

BO_ 2332225173 M2P_SUMDATA2__05: 8 MBMU
 SG_ M2P_LifeSignal_05 : 0|4@1+ (1,0) [0|15] ""  PC,SBMU
 SG_ M2P_ST_Power_05 : 4|1@1+ (1,0) [0|1] ""  PC,SBMU
 SG_ M2P_ST_Master_slave_05 : 5|1@1+ (1,0) [0|1] ""  PC,SBMU
 SG_ M2P_Status_Fan_SW_05 : 7|1@1+ (1,0) [0|1] ""  PC,SBMU
 SG_ M2P_Circuit_Breaker_05 : 8|16@1+ (1,0) [0|65535] ""  PC,SBMU
 SG_ M2P_NUM_OF_SlaveMBMU : 24|4@1+ (1,0) [0|15] ""  PC,SBMU
 SG_ M2P_RackInhabitResult : 28|2@1+ (1,0) [0|3] ""  PC,SBMU
 SG_ M2P_STofSBMUAutoCoding_05 : 30|2@1+ (1,0) [0|3] ""  PC,SBMU
 SG_ M2P_LvSelfLock : 32|1@1+ (1,0) [0|1] ""  PC,SBMU
 SG_ M2P_SbmuPwrOnFlg : 33|1@1+ (1,0) [0|1] ""  PC,SBMU
 SG_ M2P_InsulPwrOnFlg : 34|1@1+ (1,0) [0|1] ""  PC,SBMU
 SG_ M2P_HvOffReqFlg : 35|1@1+ (1,0) [0|1] ""  PC,SBMU
 SG_ M2P_HvOnAllowFlg : 36|1@1+ (1,0) [0|1] ""  PC,SBMU
 SG_ M2P_SBMULvoffAbnomal : 37|1@1+ (1,0) [0|1] ""  PC,SBMU
 SG_ M2P_LVPwrDFaultR : 38|2@1+ (1,0) [0|3] ""  PC,SBMU
 SG_ M2P_SysRunState : 40|3@1+ (1,0) [0|7] ""  PC,SBMU
 SG_ M2P_MIN_NUM_OF_ONLINE_SBMU : 43|5@1+ (1,0) [0|31] ""  PC,SBMU
 SG_ MBMU_Tank_Num_RelayOn : 48|8@1+ (1,0) [0|255] ""  PC,SBMU
 SG_ M2P_NUM_OF_SBMU : 56|8@1+ (1,0) [0|255] ""  PC

BO_ 2332225174 M2P_SUMDATA2__06: 8 MBMU
 SG_ M2P_LifeSignal_06 : 0|4@1+ (1,0) [0|15] ""  PC,SBMU
 SG_ M2P_ST_Power_06 : 4|1@1+ (1,0) [0|1] ""  PC,SBMU
 SG_ M2P_ST_Master_slave_06 : 5|1@1+ (1,0) [0|1] ""  PC,SBMU
 SG_ M2P_Status_Fan_SW_06 : 7|1@1+ (1,0) [0|1] ""  PC,SBMU
 SG_ M2P_Circuit_Breaker_06 : 8|16@1+ (1,0) [0|65535] ""  PC,SBMU
 SG_ M2P_NUM_OF_SlaveMBMU : 24|4@1+ (1,0) [0|15] ""  PC,SBMU
 SG_ M2P_RackInhabitResult : 28|2@1+ (1,0) [0|3] ""  PC,SBMU
 SG_ M2P_STofSBMUAutoCoding_06 : 30|2@1+ (1,0) [0|3] ""  PC,SBMU
 SG_ M2P_LvSelfLock : 32|1@1+ (1,0) [0|1] ""  PC,SBMU
 SG_ M2P_SbmuPwrOnFlg : 33|1@1+ (1,0) [0|1] ""  PC,SBMU
 SG_ M2P_InsulPwrOnFlg : 34|1@1+ (1,0) [0|1] ""  PC,SBMU
 SG_ M2P_HvOffReqFlg : 35|1@1+ (1,0) [0|1] ""  PC,SBMU
 SG_ M2P_HvOnAllowFlg : 36|1@1+ (1,0) [0|1] ""  PC,SBMU
 SG_ M2P_SBMULvoffAbnomal : 37|1@1+ (1,0) [0|1] ""  PC,SBMU
 SG_ M2P_LVPwrDFaultR : 38|2@1+ (1,0) [0|3] ""  PC,SBMU
 SG_ M2P_SysRunState : 40|3@1+ (1,0) [0|7] ""  PC,SBMU
 SG_ M2P_MIN_NUM_OF_ONLINE_SBMU : 43|5@1+ (1,0) [0|31] ""  PC,SBMU
 SG_ MBMU_Tank_Num_RelayOn : 48|8@1+ (1,0) [0|255] ""  PC,SBMU
 SG_ M2P_NUM_OF_SBMU : 56|8@1+ (1,0) [0|255] ""  PC

BO_ 2332225175 M2P_SUMDATA2__07: 8 MBMU
 SG_ M2P_LifeSignal_07 : 0|4@1+ (1,0) [0|15] ""  PC,SBMU
 SG_ M2P_ST_Power_07 : 4|1@1+ (1,0) [0|1] ""  PC,SBMU
 SG_ M2P_ST_Master_slave_07 : 5|1@1+ (1,0) [0|1] ""  PC,SBMU
 SG_ M2P_Status_Fan_SW_07 : 7|1@1+ (1,0) [0|1] ""  PC,SBMU
 SG_ M2P_Circuit_Breaker_07 : 8|16@1+ (1,0) [0|65535] ""  PC,SBMU
 SG_ M2P_NUM_OF_SlaveMBMU : 24|4@1+ (1,0) [0|15] ""  PC,SBMU
 SG_ M2P_RackInhabitResult : 28|2@1+ (1,0) [0|3] ""  PC,SBMU
 SG_ M2P_STofSBMUAutoCoding_07 : 30|2@1+ (1,0) [0|3] ""  PC,SBMU
 SG_ M2P_LvSelfLock : 32|1@1+ (1,0) [0|1] ""  PC,SBMU
 SG_ M2P_SbmuPwrOnFlg : 33|1@1+ (1,0) [0|1] ""  PC,SBMU
 SG_ M2P_InsulPwrOnFlg : 34|1@1+ (1,0) [0|1] ""  PC,SBMU
 SG_ M2P_HvOffReqFlg : 35|1@1+ (1,0) [0|1] ""  PC,SBMU
 SG_ M2P_HvOnAllowFlg : 36|1@1+ (1,0) [0|1] ""  PC,SBMU
 SG_ M2P_SBMULvoffAbnomal : 37|1@1+ (1,0) [0|1] ""  PC,SBMU
 SG_ M2P_LVPwrDFaultR : 38|2@1+ (1,0) [0|3] ""  PC,SBMU
 SG_ M2P_SysRunState : 40|3@1+ (1,0) [0|7] ""  PC,SBMU
 SG_ M2P_MIN_NUM_OF_ONLINE_SBMU : 43|5@1+ (1,0) [0|31] ""  PC,SBMU
 SG_ MBMU_Tank_Num_RelayOn : 48|8@1+ (1,0) [0|255] ""  PC,SBMU
 SG_ M2P_NUM_OF_SBMU : 56|8@1+ (1,0) [0|255] ""  PC

BO_ 2332225176 M2P_SUMDATA2__08: 8 MBMU
 SG_ M2P_LifeSignal_08 : 0|4@1+ (1,0) [0|15] ""  PC,SBMU
 SG_ M2P_ST_Power_08 : 4|1@1+ (1,0) [0|1] ""  PC,SBMU
 SG_ M2P_ST_Master_slave_08 : 5|1@1+ (1,0) [0|1] ""  PC,SBMU
 SG_ M2P_Status_Fan_SW_08 : 7|1@1+ (1,0) [0|1] ""  PC,SBMU
 SG_ M2P_Circuit_Breaker_08 : 8|16@1+ (1,0) [0|65535] ""  PC,SBMU
 SG_ M2P_NUM_OF_SlaveMBMU : 24|4@1+ (1,0) [0|15] ""  PC,SBMU
 SG_ M2P_RackInhabitResult : 28|2@1+ (1,0) [0|3] ""  PC,SBMU
 SG_ M2P_STofSBMUAutoCoding_08 : 30|2@1+ (1,0) [0|3] ""  PC,SBMU
 SG_ M2P_LvSelfLock : 32|1@1+ (1,0) [0|1] ""  PC,SBMU
 SG_ M2P_SbmuPwrOnFlg : 33|1@1+ (1,0) [0|1] ""  PC,SBMU
 SG_ M2P_InsulPwrOnFlg : 34|1@1+ (1,0) [0|1] ""  PC,SBMU
 SG_ M2P_HvOffReqFlg : 35|1@1+ (1,0) [0|1] ""  PC,SBMU
 SG_ M2P_HvOnAllowFlg : 36|1@1+ (1,0) [0|1] ""  PC,SBMU
 SG_ M2P_SBMULvoffAbnomal : 37|1@1+ (1,0) [0|1] ""  PC,SBMU
 SG_ M2P_LVPwrDFaultR : 38|2@1+ (1,0) [0|3] ""  PC,SBMU
 SG_ M2P_SysRunState : 40|3@1+ (1,0) [0|7] ""  PC,SBMU
 SG_ M2P_MIN_NUM_OF_ONLINE_SBMU : 43|5@1+ (1,0) [0|31] ""  PC,SBMU
 SG_ MBMU_Tank_Num_RelayOn : 48|8@1+ (1,0) [0|255] ""  PC,SBMU
 SG_ M2P_NUM_OF_SBMU : 56|8@1+ (1,0) [0|255] ""  PC

BO_ 2332225177 M2P_SUMDATA2__09: 8 MBMU
 SG_ M2P_LifeSignal_09 : 0|4@1+ (1,0) [0|15] ""  PC,SBMU
 SG_ M2P_ST_Power_09 : 4|1@1+ (1,0) [0|1] ""  PC,SBMU
 SG_ M2P_ST_Master_slave_09 : 5|1@1+ (1,0) [0|1] ""  PC,SBMU
 SG_ M2P_Status_Fan_SW_09 : 7|1@1+ (1,0) [0|1] ""  PC,SBMU
 SG_ M2P_Circuit_Breaker_09 : 8|16@1+ (1,0) [0|65535] ""  PC,SBMU
 SG_ M2P_NUM_OF_SlaveMBMU : 24|4@1+ (1,0) [0|15] ""  PC,SBMU
 SG_ M2P_RackInhabitResult : 28|2@1+ (1,0) [0|3] ""  PC,SBMU
 SG_ M2P_STofSBMUAutoCoding_09 : 30|2@1+ (1,0) [0|3] ""  PC,SBMU
 SG_ M2P_LvSelfLock : 32|1@1+ (1,0) [0|1] ""  PC,SBMU
 SG_ M2P_SbmuPwrOnFlg : 33|1@1+ (1,0) [0|1] ""  PC,SBMU
 SG_ M2P_InsulPwrOnFlg : 34|1@1+ (1,0) [0|1] ""  PC,SBMU
 SG_ M2P_HvOffReqFlg : 35|1@1+ (1,0) [0|1] ""  PC,SBMU
 SG_ M2P_HvOnAllowFlg : 36|1@1+ (1,0) [0|1] ""  PC,SBMU
 SG_ M2P_SBMULvoffAbnomal : 37|1@1+ (1,0) [0|1] ""  PC,SBMU
 SG_ M2P_LVPwrDFaultR : 38|2@1+ (1,0) [0|3] ""  PC,SBMU
 SG_ M2P_SysRunState : 40|3@1+ (1,0) [0|7] ""  PC,SBMU
 SG_ M2P_MIN_NUM_OF_ONLINE_SBMU : 43|5@1+ (1,0) [0|31] ""  PC,SBMU
 SG_ MBMU_Tank_Num_RelayOn : 48|8@1+ (1,0) [0|255] ""  PC,SBMU
 SG_ M2P_NUM_OF_SBMU : 56|8@1+ (1,0) [0|255] ""  PC

BO_ 2332225178 M2P_SUMDATA2__10: 8 MBMU
 SG_ M2P_LifeSignal_10 : 0|4@1+ (1,0) [0|15] ""  PC,SBMU
 SG_ M2P_ST_Power_10 : 4|1@1+ (1,0) [0|1] ""  PC,SBMU
 SG_ M2P_ST_Master_slave_10 : 5|1@1+ (1,0) [0|1] ""  PC,SBMU
 SG_ M2P_Status_Fan_SW_10 : 7|1@1+ (1,0) [0|1] ""  PC,SBMU
 SG_ M2P_Circuit_Breaker_10 : 8|16@1+ (1,0) [0|65535] ""  PC,SBMU
 SG_ M2P_NUM_OF_SlaveMBMU : 24|4@1+ (1,0) [0|15] ""  PC,SBMU
 SG_ M2P_RackInhabitResult : 28|2@1+ (1,0) [0|3] ""  PC,SBMU
 SG_ M2P_STofSBMUAutoCoding_10 : 30|2@1+ (1,0) [0|3] ""  PC,SBMU
 SG_ M2P_LvSelfLock : 32|1@1+ (1,0) [0|1] ""  PC,SBMU
 SG_ M2P_SbmuPwrOnFlg : 33|1@1+ (1,0) [0|1] ""  PC,SBMU
 SG_ M2P_InsulPwrOnFlg : 34|1@1+ (1,0) [0|1] ""  PC,SBMU
 SG_ M2P_HvOffReqFlg : 35|1@1+ (1,0) [0|1] ""  PC,SBMU
 SG_ M2P_HvOnAllowFlg : 36|1@1+ (1,0) [0|1] ""  PC,SBMU
 SG_ M2P_SBMULvoffAbnomal : 37|1@1+ (1,0) [0|1] ""  PC,SBMU
 SG_ M2P_LVPwrDFaultR : 38|2@1+ (1,0) [0|3] ""  PC,SBMU
 SG_ M2P_SysRunState : 40|3@1+ (1,0) [0|7] ""  PC,SBMU
 SG_ M2P_MIN_NUM_OF_ONLINE_SBMU : 43|5@1+ (1,0) [0|31] ""  PC,SBMU
 SG_ MBMU_Tank_Num_RelayOn : 48|8@1+ (1,0) [0|255] ""  PC,SBMU
 SG_ M2P_NUM_OF_SBMU : 56|8@1+ (1,0) [0|255] ""  PC

BO_ 2332225179 M2P_SUMDATA2__11: 8 MBMU
 SG_ M2P_LifeSignal_11 : 0|4@1+ (1,0) [0|15] ""  PC,SBMU
 SG_ M2P_ST_Power_11 : 4|1@1+ (1,0) [0|1] ""  PC,SBMU
 SG_ M2P_ST_Master_slave_11 : 5|1@1+ (1,0) [0|1] ""  PC,SBMU
 SG_ M2P_Status_Fan_SW_11 : 7|1@1+ (1,0) [0|1] ""  PC,SBMU
 SG_ M2P_Circuit_Breaker_11 : 8|16@1+ (1,0) [0|65535] ""  PC,SBMU
 SG_ M2P_NUM_OF_SlaveMBMU : 24|4@1+ (1,0) [0|15] ""  PC,SBMU
 SG_ M2P_RackInhabitResult : 28|2@1+ (1,0) [0|3] ""  PC,SBMU
 SG_ M2P_STofSBMUAutoCoding_11 : 30|2@1+ (1,0) [0|3] ""  PC,SBMU
 SG_ M2P_LvSelfLock : 32|1@1+ (1,0) [0|1] ""  PC,SBMU
 SG_ M2P_SbmuPwrOnFlg : 33|1@1+ (1,0) [0|1] ""  PC,SBMU
 SG_ M2P_InsulPwrOnFlg : 34|1@1+ (1,0) [0|1] ""  PC,SBMU
 SG_ M2P_HvOffReqFlg : 35|1@1+ (1,0) [0|1] ""  PC,SBMU
 SG_ M2P_HvOnAllowFlg : 36|1@1+ (1,0) [0|1] ""  PC,SBMU
 SG_ M2P_SBMULvoffAbnomal : 37|1@1+ (1,0) [0|1] ""  PC,SBMU
 SG_ M2P_LVPwrDFaultR : 38|2@1+ (1,0) [0|3] ""  PC,SBMU
 SG_ M2P_SysRunState : 40|3@1+ (1,0) [0|7] ""  PC,SBMU
 SG_ M2P_MIN_NUM_OF_ONLINE_SBMU : 43|5@1+ (1,0) [0|31] ""  PC,SBMU
 SG_ MBMU_Tank_Num_RelayOn : 48|8@1+ (1,0) [0|255] ""  PC,SBMU
 SG_ M2P_NUM_OF_SBMU : 56|8@1+ (1,0) [0|255] ""  PC

BO_ 2332225180 M2P_SUMDATA2__12: 8 MBMU
 SG_ M2P_LifeSignal_12 : 0|4@1+ (1,0) [0|15] ""  PC,SBMU
 SG_ M2P_ST_Power_12 : 4|1@1+ (1,0) [0|1] ""  PC,SBMU
 SG_ M2P_ST_Master_slave_12 : 5|1@1+ (1,0) [0|1] ""  PC,SBMU
 SG_ M2P_Status_Fan_SW_12 : 7|1@1+ (1,0) [0|1] ""  PC,SBMU
 SG_ M2P_Circuit_Breaker_12 : 8|16@1+ (1,0) [0|65535] ""  PC,SBMU
 SG_ M2P_NUM_OF_SlaveMBMU : 24|4@1+ (1,0) [0|15] ""  PC,SBMU
 SG_ M2P_RackInhabitResult : 28|2@1+ (1,0) [0|3] ""  PC,SBMU
 SG_ M2P_STofSBMUAutoCoding_12 : 30|2@1+ (1,0) [0|3] ""  PC,SBMU
 SG_ M2P_LvSelfLock : 32|1@1+ (1,0) [0|1] ""  PC,SBMU
 SG_ M2P_SbmuPwrOnFlg : 33|1@1+ (1,0) [0|1] ""  PC,SBMU
 SG_ M2P_InsulPwrOnFlg : 34|1@1+ (1,0) [0|1] ""  PC,SBMU
 SG_ M2P_HvOffReqFlg : 35|1@1+ (1,0) [0|1] ""  PC,SBMU
 SG_ M2P_HvOnAllowFlg : 36|1@1+ (1,0) [0|1] ""  PC,SBMU
 SG_ M2P_SBMULvoffAbnomal : 37|1@1+ (1,0) [0|1] ""  PC,SBMU
 SG_ M2P_LVPwrDFaultR : 38|2@1+ (1,0) [0|3] ""  PC,SBMU
 SG_ M2P_SysRunState : 40|3@1+ (1,0) [0|7] ""  PC,SBMU
 SG_ M2P_MIN_NUM_OF_ONLINE_SBMU : 43|5@1+ (1,0) [0|31] ""  PC,SBMU
 SG_ MBMU_Tank_Num_RelayOn : 48|8@1+ (1,0) [0|255] ""  PC,SBMU
 SG_ M2P_NUM_OF_SBMU : 56|8@1+ (1,0) [0|255] ""  PC

BO_ 2332225181 M2P_SUMDATA2__13: 8 MBMU
 SG_ M2P_LifeSignal_13 : 0|4@1+ (1,0) [0|15] ""  PC,SBMU
 SG_ M2P_ST_Power_13 : 4|1@1+ (1,0) [0|1] ""  PC,SBMU
 SG_ M2P_ST_Master_slave_13 : 5|1@1+ (1,0) [0|1] ""  PC,SBMU
 SG_ M2P_Status_Fan_SW_13 : 7|1@1+ (1,0) [0|1] ""  PC,SBMU
 SG_ M2P_Circuit_Breaker_13 : 8|16@1+ (1,0) [0|65535] ""  PC,SBMU
 SG_ M2P_NUM_OF_SlaveMBMU : 24|4@1+ (1,0) [0|15] ""  PC,SBMU
 SG_ M2P_RackInhabitResult : 28|2@1+ (1,0) [0|3] ""  PC,SBMU
 SG_ M2P_STofSBMUAutoCoding_13 : 30|2@1+ (1,0) [0|3] ""  PC,SBMU
 SG_ M2P_LvSelfLock : 32|1@1+ (1,0) [0|1] ""  PC,SBMU
 SG_ M2P_SbmuPwrOnFlg : 33|1@1+ (1,0) [0|1] ""  PC,SBMU
 SG_ M2P_InsulPwrOnFlg : 34|1@1+ (1,0) [0|1] ""  PC,SBMU
 SG_ M2P_HvOffReqFlg : 35|1@1+ (1,0) [0|1] ""  PC,SBMU
 SG_ M2P_HvOnAllowFlg : 36|1@1+ (1,0) [0|1] ""  PC,SBMU
 SG_ M2P_SBMULvoffAbnomal : 37|1@1+ (1,0) [0|1] ""  PC,SBMU
 SG_ M2P_LVPwrDFaultR : 38|2@1+ (1,0) [0|3] ""  PC,SBMU
 SG_ M2P_SysRunState : 40|3@1+ (1,0) [0|7] ""  PC,SBMU
 SG_ M2P_MIN_NUM_OF_ONLINE_SBMU : 43|5@1+ (1,0) [0|31] ""  PC,SBMU
 SG_ MBMU_Tank_Num_RelayOn : 48|8@1+ (1,0) [0|255] ""  PC,SBMU
 SG_ M2P_NUM_OF_SBMU : 56|8@1+ (1,0) [0|255] ""  PC

BO_ 2332225182 M2P_SUMDATA2__14: 8 MBMU
 SG_ M2P_LifeSignal_14 : 0|4@1+ (1,0) [0|15] ""  PC,SBMU
 SG_ M2P_ST_Power_14 : 4|1@1+ (1,0) [0|1] ""  PC,SBMU
 SG_ M2P_ST_Master_slave_14 : 5|1@1+ (1,0) [0|1] ""  PC,SBMU
 SG_ M2P_Status_Fan_SW_14 : 7|1@1+ (1,0) [0|1] ""  PC,SBMU
 SG_ M2P_Circuit_Breaker_14 : 8|16@1+ (1,0) [0|65535] ""  PC,SBMU
 SG_ M2P_NUM_OF_SlaveMBMU : 24|4@1+ (1,0) [0|15] ""  PC,SBMU
 SG_ M2P_RackInhabitResult : 28|2@1+ (1,0) [0|3] ""  PC,SBMU
 SG_ M2P_STofSBMUAutoCoding_14 : 30|2@1+ (1,0) [0|3] ""  PC,SBMU
 SG_ M2P_LvSelfLock : 32|1@1+ (1,0) [0|1] ""  PC,SBMU
 SG_ M2P_SbmuPwrOnFlg : 33|1@1+ (1,0) [0|1] ""  PC,SBMU
 SG_ M2P_InsulPwrOnFlg : 34|1@1+ (1,0) [0|1] ""  PC,SBMU
 SG_ M2P_HvOffReqFlg : 35|1@1+ (1,0) [0|1] ""  PC,SBMU
 SG_ M2P_HvOnAllowFlg : 36|1@1+ (1,0) [0|1] ""  PC,SBMU
 SG_ M2P_SBMULvoffAbnomal : 37|1@1+ (1,0) [0|1] ""  PC,SBMU
 SG_ M2P_LVPwrDFaultR : 38|2@1+ (1,0) [0|3] ""  PC,SBMU
 SG_ M2P_SysRunState : 40|3@1+ (1,0) [0|7] ""  PC,SBMU
 SG_ M2P_MIN_NUM_OF_ONLINE_SBMU : 43|5@1+ (1,0) [0|31] ""  PC,SBMU
 SG_ MBMU_Tank_Num_RelayOn : 48|8@1+ (1,0) [0|255] ""  PC,SBMU
 SG_ M2P_NUM_OF_SBMU : 56|8@1+ (1,0) [0|255] ""  PC

BO_ 2332225183 M2P_SUMDATA2__15: 8 MBMU
 SG_ M2P_LifeSignal_15 : 0|4@1+ (1,0) [0|15] ""  PC,SBMU
 SG_ M2P_ST_Power_15 : 4|1@1+ (1,0) [0|1] ""  PC,SBMU
 SG_ M2P_ST_Master_slave_15 : 5|1@1+ (1,0) [0|1] ""  PC,SBMU
 SG_ M2P_Status_Fan_SW_15 : 7|1@1+ (1,0) [0|1] ""  PC,SBMU
 SG_ M2P_Circuit_Breaker_15 : 8|16@1+ (1,0) [0|65535] ""  PC,SBMU
 SG_ M2P_NUM_OF_SlaveMBMU : 24|4@1+ (1,0) [0|15] ""  PC,SBMU
 SG_ M2P_RackInhabitResult : 28|2@1+ (1,0) [0|3] ""  PC,SBMU
 SG_ M2P_STofSBMUAutoCoding_15 : 30|2@1+ (1,0) [0|3] ""  PC,SBMU
 SG_ M2P_LvSelfLock : 32|1@1+ (1,0) [0|1] ""  PC,SBMU
 SG_ M2P_SbmuPwrOnFlg : 33|1@1+ (1,0) [0|1] ""  PC,SBMU
 SG_ M2P_InsulPwrOnFlg : 34|1@1+ (1,0) [0|1] ""  PC,SBMU
 SG_ M2P_HvOffReqFlg : 35|1@1+ (1,0) [0|1] ""  PC,SBMU
 SG_ M2P_HvOnAllowFlg : 36|1@1+ (1,0) [0|1] ""  PC,SBMU
 SG_ M2P_SBMULvoffAbnomal : 37|1@1+ (1,0) [0|1] ""  PC,SBMU
 SG_ M2P_LVPwrDFaultR : 38|2@1+ (1,0) [0|3] ""  PC,SBMU
 SG_ M2P_SysRunState : 40|3@1+ (1,0) [0|7] ""  PC,SBMU
 SG_ M2P_MIN_NUM_OF_ONLINE_SBMU : 43|5@1+ (1,0) [0|31] ""  PC,SBMU
 SG_ MBMU_Tank_Num_RelayOn : 48|8@1+ (1,0) [0|255] ""  PC,SBMU
 SG_ M2P_NUM_OF_SBMU : 56|8@1+ (1,0) [0|255] ""  PC

BO_ 2332225184 M2P_SUMDATA2__16: 8 MBMU
 SG_ M2P_LifeSignal_16 : 0|4@1+ (1,0) [0|15] ""  PC,SBMU
 SG_ M2P_ST_Power_16 : 4|1@1+ (1,0) [0|1] ""  PC,SBMU
 SG_ M2P_ST_Master_slave_16 : 5|1@1+ (1,0) [0|1] ""  PC,SBMU
 SG_ M2P_Status_Fan_SW_16 : 7|1@1+ (1,0) [0|1] ""  PC,SBMU
 SG_ M2P_Circuit_Breaker_16 : 8|16@1+ (1,0) [0|65535] ""  PC,SBMU
 SG_ M2P_NUM_OF_SlaveMBMU : 24|4@1+ (1,0) [0|15] ""  PC,SBMU
 SG_ M2P_RackInhabitResult : 28|2@1+ (1,0) [0|3] ""  PC,SBMU
 SG_ M2P_STofSBMUAutoCoding_16 : 30|2@1+ (1,0) [0|3] ""  PC,SBMU
 SG_ M2P_LvSelfLock : 32|1@1+ (1,0) [0|1] ""  PC,SBMU
 SG_ M2P_SbmuPwrOnFlg : 33|1@1+ (1,0) [0|1] ""  PC,SBMU
 SG_ M2P_InsulPwrOnFlg : 34|1@1+ (1,0) [0|1] ""  PC,SBMU
 SG_ M2P_HvOffReqFlg : 35|1@1+ (1,0) [0|1] ""  PC,SBMU
 SG_ M2P_HvOnAllowFlg : 36|1@1+ (1,0) [0|1] ""  PC,SBMU
 SG_ M2P_SBMULvoffAbnomal : 37|1@1+ (1,0) [0|1] ""  PC,SBMU
 SG_ M2P_LVPwrDFaultR : 38|2@1+ (1,0) [0|3] ""  PC,SBMU
 SG_ M2P_SysRunState : 40|3@1+ (1,0) [0|7] ""  PC,SBMU
 SG_ M2P_MIN_NUM_OF_ONLINE_SBMU : 43|5@1+ (1,0) [0|31] ""  PC,SBMU
 SG_ MBMU_Tank_Num_RelayOn : 48|8@1+ (1,0) [0|255] ""  PC,SBMU
 SG_ M2P_NUM_OF_SBMU : 56|8@1+ (1,0) [0|255] ""  PC

BO_ 2332225185 M2P_SUMDATA2__17: 8 MBMU
 SG_ M2P_LifeSignal_17 : 0|4@1+ (1,0) [0|15] ""  PC,SBMU
 SG_ M2P_ST_Power_17 : 4|1@1+ (1,0) [0|1] ""  PC,SBMU
 SG_ M2P_ST_Master_slave_17 : 5|1@1+ (1,0) [0|1] ""  PC,SBMU
 SG_ M2P_Status_Fan_SW_17 : 7|1@1+ (1,0) [0|1] ""  PC,SBMU
 SG_ M2P_Circuit_Breaker_17 : 8|16@1+ (1,0) [0|65535] ""  PC,SBMU
 SG_ M2P_NUM_OF_SlaveMBMU : 24|4@1+ (1,0) [0|15] ""  PC,SBMU
 SG_ M2P_RackInhabitResult : 28|2@1+ (1,0) [0|3] ""  PC,SBMU
 SG_ M2P_STofSBMUAutoCoding_17 : 30|2@1+ (1,0) [0|3] ""  PC,SBMU
 SG_ M2P_LvSelfLock : 32|1@1+ (1,0) [0|1] ""  PC,SBMU
 SG_ M2P_SbmuPwrOnFlg : 33|1@1+ (1,0) [0|1] ""  PC,SBMU
 SG_ M2P_InsulPwrOnFlg : 34|1@1+ (1,0) [0|1] ""  PC,SBMU
 SG_ M2P_HvOffReqFlg : 35|1@1+ (1,0) [0|1] ""  PC,SBMU
 SG_ M2P_HvOnAllowFlg : 36|1@1+ (1,0) [0|1] ""  PC,SBMU
 SG_ M2P_SBMULvoffAbnomal : 37|1@1+ (1,0) [0|1] ""  PC,SBMU
 SG_ M2P_LVPwrDFaultR : 38|2@1+ (1,0) [0|3] ""  PC,SBMU
 SG_ M2P_SysRunState : 40|3@1+ (1,0) [0|7] ""  PC,SBMU
 SG_ M2P_MIN_NUM_OF_ONLINE_SBMU : 43|5@1+ (1,0) [0|31] ""  PC,SBMU
 SG_ MBMU_Tank_Num_RelayOn : 48|8@1+ (1,0) [0|255] ""  PC,SBMU
 SG_ M2P_NUM_OF_SBMU : 56|8@1+ (1,0) [0|255] ""  PC

BO_ 2332225186 M2P_SUMDATA2__18: 8 MBMU
 SG_ M2P_LifeSignal_18 : 0|4@1+ (1,0) [0|15] ""  PC,SBMU
 SG_ M2P_ST_Power_18 : 4|1@1+ (1,0) [0|1] ""  PC,SBMU
 SG_ M2P_ST_Master_slave_18 : 5|1@1+ (1,0) [0|1] ""  PC,SBMU
 SG_ M2P_Status_Fan_SW_18 : 7|1@1+ (1,0) [0|1] ""  PC,SBMU
 SG_ M2P_Circuit_Breaker_18 : 8|16@1+ (1,0) [0|65535] ""  PC,SBMU
 SG_ M2P_NUM_OF_SlaveMBMU : 24|4@1+ (1,0) [0|15] ""  PC,SBMU
 SG_ M2P_RackInhabitResult : 28|2@1+ (1,0) [0|3] ""  PC,SBMU
 SG_ M2P_STofSBMUAutoCoding_18 : 30|2@1+ (1,0) [0|3] ""  PC,SBMU
 SG_ M2P_LvSelfLock : 32|1@1+ (1,0) [0|1] ""  PC,SBMU
 SG_ M2P_SbmuPwrOnFlg : 33|1@1+ (1,0) [0|1] ""  PC,SBMU
 SG_ M2P_InsulPwrOnFlg : 34|1@1+ (1,0) [0|1] ""  PC,SBMU
 SG_ M2P_HvOffReqFlg : 35|1@1+ (1,0) [0|1] ""  PC,SBMU
 SG_ M2P_HvOnAllowFlg : 36|1@1+ (1,0) [0|1] ""  PC,SBMU
 SG_ M2P_SBMULvoffAbnomal : 37|1@1+ (1,0) [0|1] ""  PC,SBMU
 SG_ M2P_LVPwrDFaultR : 38|2@1+ (1,0) [0|3] ""  PC,SBMU
 SG_ M2P_SysRunState : 40|3@1+ (1,0) [0|7] ""  PC,SBMU
 SG_ M2P_MIN_NUM_OF_ONLINE_SBMU : 43|5@1+ (1,0) [0|31] ""  PC,SBMU
 SG_ MBMU_Tank_Num_RelayOn : 48|8@1+ (1,0) [0|255] ""  PC,SBMU
 SG_ M2P_NUM_OF_SBMU : 56|8@1+ (1,0) [0|255] ""  PC

BO_ 2332225187 M2P_SUMDATA2__19: 8 MBMU
 SG_ M2P_LifeSignal_19 : 0|4@1+ (1,0) [0|15] ""  PC,SBMU
 SG_ M2P_ST_Power_19 : 4|1@1+ (1,0) [0|1] ""  PC,SBMU
 SG_ M2P_ST_Master_slave_19 : 5|1@1+ (1,0) [0|1] ""  PC,SBMU
 SG_ M2P_Status_Fan_SW_19 : 7|1@1+ (1,0) [0|1] ""  PC,SBMU
 SG_ M2P_Circuit_Breaker_19 : 8|16@1+ (1,0) [0|65535] ""  PC,SBMU
 SG_ M2P_NUM_OF_SlaveMBMU : 24|4@1+ (1,0) [0|15] ""  PC,SBMU
 SG_ M2P_RackInhabitResult : 28|2@1+ (1,0) [0|3] ""  PC,SBMU
 SG_ M2P_STofSBMUAutoCoding_19 : 30|2@1+ (1,0) [0|3] ""  PC,SBMU
 SG_ M2P_LvSelfLock : 32|1@1+ (1,0) [0|1] ""  PC,SBMU
 SG_ M2P_SbmuPwrOnFlg : 33|1@1+ (1,0) [0|1] ""  PC,SBMU
 SG_ M2P_InsulPwrOnFlg : 34|1@1+ (1,0) [0|1] ""  PC,SBMU
 SG_ M2P_HvOffReqFlg : 35|1@1+ (1,0) [0|1] ""  PC,SBMU
 SG_ M2P_HvOnAllowFlg : 36|1@1+ (1,0) [0|1] ""  PC,SBMU
 SG_ M2P_SBMULvoffAbnomal : 37|1@1+ (1,0) [0|1] ""  PC,SBMU
 SG_ M2P_LVPwrDFaultR : 38|2@1+ (1,0) [0|3] ""  PC,SBMU
 SG_ M2P_SysRunState : 40|3@1+ (1,0) [0|7] ""  PC,SBMU
 SG_ M2P_MIN_NUM_OF_ONLINE_SBMU : 43|5@1+ (1,0) [0|31] ""  PC,SBMU
 SG_ MBMU_Tank_Num_RelayOn : 48|8@1+ (1,0) [0|255] ""  PC,SBMU
 SG_ M2P_NUM_OF_SBMU : 56|8@1+ (1,0) [0|255] ""  PC

BO_ 2332225188 M2P_SUMDATA2__20: 8 MBMU
 SG_ M2P_LifeSignal_20 : 0|4@1+ (1,0) [0|15] ""  PC,SBMU
 SG_ M2P_ST_Power_20 : 4|1@1+ (1,0) [0|1] ""  PC,SBMU
 SG_ M2P_ST_Master_slave_20 : 5|1@1+ (1,0) [0|1] ""  PC,SBMU
 SG_ M2P_Status_Fan_SW_20 : 7|1@1+ (1,0) [0|1] ""  PC,SBMU
 SG_ M2P_Circuit_Breaker_20 : 8|16@1+ (1,0) [0|65535] ""  PC,SBMU
 SG_ M2P_NUM_OF_SlaveMBMU : 24|4@1+ (1,0) [0|15] ""  PC,SBMU
 SG_ M2P_RackInhabitResult : 28|2@1+ (1,0) [0|3] ""  PC,SBMU
 SG_ M2P_STofSBMUAutoCoding_20 : 30|2@1+ (1,0) [0|3] ""  PC,SBMU
 SG_ M2P_LvSelfLock : 32|1@1+ (1,0) [0|1] ""  PC,SBMU
 SG_ M2P_SbmuPwrOnFlg : 33|1@1+ (1,0) [0|1] ""  PC,SBMU
 SG_ M2P_InsulPwrOnFlg : 34|1@1+ (1,0) [0|1] ""  PC,SBMU
 SG_ M2P_HvOffReqFlg : 35|1@1+ (1,0) [0|1] ""  PC,SBMU
 SG_ M2P_HvOnAllowFlg : 36|1@1+ (1,0) [0|1] ""  PC,SBMU
 SG_ M2P_SBMULvoffAbnomal : 37|1@1+ (1,0) [0|1] ""  PC,SBMU
 SG_ M2P_LVPwrDFaultR : 38|2@1+ (1,0) [0|3] ""  PC,SBMU
 SG_ M2P_SysRunState : 40|3@1+ (1,0) [0|7] ""  PC,SBMU
 SG_ M2P_MIN_NUM_OF_ONLINE_SBMU : 43|5@1+ (1,0) [0|31] ""  PC,SBMU
 SG_ MBMU_Tank_Num_RelayOn : 48|8@1+ (1,0) [0|255] ""  PC,SBMU
 SG_ M2P_NUM_OF_SBMU : 56|8@1+ (1,0) [0|255] ""  PC

BO_ 2332225189 M2P_SUMDATA2__21: 8 MBMU
 SG_ M2P_LifeSignal_21 : 0|4@1+ (1,0) [0|15] ""  PC,SBMU
 SG_ M2P_ST_Power_21 : 4|1@1+ (1,0) [0|1] ""  PC,SBMU
 SG_ M2P_ST_Master_slave_21 : 5|1@1+ (1,0) [0|1] ""  PC,SBMU
 SG_ M2P_Status_Fan_SW_21 : 7|1@1+ (1,0) [0|1] ""  PC,SBMU
 SG_ M2P_Circuit_Breaker_21 : 8|16@1+ (1,0) [0|65535] ""  PC,SBMU
 SG_ M2P_NUM_OF_SlaveMBMU : 24|4@1+ (1,0) [0|15] ""  PC,SBMU
 SG_ M2P_RackInhabitResult : 28|2@1+ (1,0) [0|3] ""  PC,SBMU
 SG_ M2P_STofSBMUAutoCoding_21 : 30|2@1+ (1,0) [0|3] ""  PC,SBMU
 SG_ M2P_LvSelfLock : 32|1@1+ (1,0) [0|1] ""  PC,SBMU
 SG_ M2P_SbmuPwrOnFlg : 33|1@1+ (1,0) [0|1] ""  PC,SBMU
 SG_ M2P_InsulPwrOnFlg : 34|1@1+ (1,0) [0|1] ""  PC,SBMU
 SG_ M2P_HvOffReqFlg : 35|1@1+ (1,0) [0|1] ""  PC,SBMU
 SG_ M2P_HvOnAllowFlg : 36|1@1+ (1,0) [0|1] ""  PC,SBMU
 SG_ M2P_SBMULvoffAbnomal : 37|1@1+ (1,0) [0|1] ""  PC,SBMU
 SG_ M2P_LVPwrDFaultR : 38|2@1+ (1,0) [0|3] ""  PC,SBMU
 SG_ M2P_SysRunState : 40|3@1+ (1,0) [0|7] ""  PC,SBMU
 SG_ M2P_MIN_NUM_OF_ONLINE_SBMU : 43|5@1+ (1,0) [0|31] ""  PC,SBMU
 SG_ MBMU_Tank_Num_RelayOn : 48|8@1+ (1,0) [0|255] ""  PC,SBMU
 SG_ M2P_NUM_OF_SBMU : 56|8@1+ (1,0) [0|255] ""  PC

BO_ 2332225190 M2P_SUMDATA2__22: 8 MBMU
 SG_ M2P_LifeSignal_22 : 0|4@1+ (1,0) [0|15] ""  PC,SBMU
 SG_ M2P_ST_Power_22 : 4|1@1+ (1,0) [0|1] ""  PC,SBMU
 SG_ M2P_ST_Master_slave_22 : 5|1@1+ (1,0) [0|1] ""  PC,SBMU
 SG_ M2P_Status_Fan_SW_22 : 7|1@1+ (1,0) [0|1] ""  PC,SBMU
 SG_ M2P_Circuit_Breaker_22 : 8|16@1+ (1,0) [0|65535] ""  PC,SBMU
 SG_ M2P_NUM_OF_SlaveMBMU : 24|4@1+ (1,0) [0|15] ""  PC,SBMU
 SG_ M2P_RackInhabitResult : 28|2@1+ (1,0) [0|3] ""  PC,SBMU
 SG_ M2P_STofSBMUAutoCoding_22 : 30|2@1+ (1,0) [0|3] ""  PC,SBMU
 SG_ M2P_LvSelfLock : 32|1@1+ (1,0) [0|1] ""  PC,SBMU
 SG_ M2P_SbmuPwrOnFlg : 33|1@1+ (1,0) [0|1] ""  PC,SBMU
 SG_ M2P_InsulPwrOnFlg : 34|1@1+ (1,0) [0|1] ""  PC,SBMU
 SG_ M2P_HvOffReqFlg : 35|1@1+ (1,0) [0|1] ""  PC,SBMU
 SG_ M2P_HvOnAllowFlg : 36|1@1+ (1,0) [0|1] ""  PC,SBMU
 SG_ M2P_SBMULvoffAbnomal : 37|1@1+ (1,0) [0|1] ""  PC,SBMU
 SG_ M2P_LVPwrDFaultR : 38|2@1+ (1,0) [0|3] ""  PC,SBMU
 SG_ M2P_SysRunState : 40|3@1+ (1,0) [0|7] ""  PC,SBMU
 SG_ M2P_MIN_NUM_OF_ONLINE_SBMU : 43|5@1+ (1,0) [0|31] ""  PC,SBMU
 SG_ MBMU_Tank_Num_RelayOn : 48|8@1+ (1,0) [0|255] ""  PC,SBMU
 SG_ M2P_NUM_OF_SBMU : 56|8@1+ (1,0) [0|255] ""  PC

BO_ 2332225191 M2P_SUMDATA2__23: 8 MBMU
 SG_ M2P_LifeSignal_23 : 0|4@1+ (1,0) [0|15] ""  PC,SBMU
 SG_ M2P_ST_Power_23 : 4|1@1+ (1,0) [0|1] ""  PC,SBMU
 SG_ M2P_ST_Master_slave_23 : 5|1@1+ (1,0) [0|1] ""  PC,SBMU
 SG_ M2P_Status_Fan_SW_23 : 7|1@1+ (1,0) [0|1] ""  PC,SBMU
 SG_ M2P_Circuit_Breaker_23 : 8|16@1+ (1,0) [0|65535] ""  PC,SBMU
 SG_ M2P_NUM_OF_SlaveMBMU : 24|4@1+ (1,0) [0|15] ""  PC,SBMU
 SG_ M2P_RackInhabitResult : 28|2@1+ (1,0) [0|3] ""  PC,SBMU
 SG_ M2P_STofSBMUAutoCoding_23 : 30|2@1+ (1,0) [0|3] ""  PC,SBMU
 SG_ M2P_LvSelfLock : 32|1@1+ (1,0) [0|1] ""  PC,SBMU
 SG_ M2P_SbmuPwrOnFlg : 33|1@1+ (1,0) [0|1] ""  PC,SBMU
 SG_ M2P_InsulPwrOnFlg : 34|1@1+ (1,0) [0|1] ""  PC,SBMU
 SG_ M2P_HvOffReqFlg : 35|1@1+ (1,0) [0|1] ""  PC,SBMU
 SG_ M2P_HvOnAllowFlg : 36|1@1+ (1,0) [0|1] ""  PC,SBMU
 SG_ M2P_SBMULvoffAbnomal : 37|1@1+ (1,0) [0|1] ""  PC,SBMU
 SG_ M2P_LVPwrDFaultR : 38|2@1+ (1,0) [0|3] ""  PC,SBMU
 SG_ M2P_SysRunState : 40|3@1+ (1,0) [0|7] ""  PC,SBMU
 SG_ M2P_MIN_NUM_OF_ONLINE_SBMU : 43|5@1+ (1,0) [0|31] ""  PC,SBMU
 SG_ MBMU_Tank_Num_RelayOn : 48|8@1+ (1,0) [0|255] ""  PC,SBMU
 SG_ M2P_NUM_OF_SBMU : 56|8@1+ (1,0) [0|255] ""  PC

BO_ 2332225192 M2P_SUMDATA2__24: 8 MBMU
 SG_ M2P_LifeSignal_24 : 0|4@1+ (1,0) [0|15] ""  PC,SBMU
 SG_ M2P_ST_Power_24 : 4|1@1+ (1,0) [0|1] ""  PC,SBMU
 SG_ M2P_ST_Master_slave_24 : 5|1@1+ (1,0) [0|1] ""  PC,SBMU
 SG_ M2P_Status_Fan_SW_24 : 7|1@1+ (1,0) [0|1] ""  PC,SBMU
 SG_ M2P_Circuit_Breaker_24 : 8|16@1+ (1,0) [0|65535] ""  PC,SBMU
 SG_ M2P_NUM_OF_SlaveMBMU : 24|4@1+ (1,0) [0|15] ""  PC,SBMU
 SG_ M2P_RackInhabitResult : 28|2@1+ (1,0) [0|3] ""  PC,SBMU
 SG_ M2P_STofSBMUAutoCoding_24 : 30|2@1+ (1,0) [0|3] ""  PC,SBMU
 SG_ M2P_LvSelfLock : 32|1@1+ (1,0) [0|1] ""  PC,SBMU
 SG_ M2P_SbmuPwrOnFlg : 33|1@1+ (1,0) [0|1] ""  PC,SBMU
 SG_ M2P_InsulPwrOnFlg : 34|1@1+ (1,0) [0|1] ""  PC,SBMU
 SG_ M2P_HvOffReqFlg : 35|1@1+ (1,0) [0|1] ""  PC,SBMU
 SG_ M2P_HvOnAllowFlg : 36|1@1+ (1,0) [0|1] ""  PC,SBMU
 SG_ M2P_SBMULvoffAbnomal : 37|1@1+ (1,0) [0|1] ""  PC,SBMU
 SG_ M2P_LVPwrDFaultR : 38|2@1+ (1,0) [0|3] ""  PC,SBMU
 SG_ M2P_SysRunState : 40|3@1+ (1,0) [0|7] ""  PC,SBMU
 SG_ M2P_MIN_NUM_OF_ONLINE_SBMU : 43|5@1+ (1,0) [0|31] ""  PC,SBMU
 SG_ MBMU_Tank_Num_RelayOn : 48|8@1+ (1,0) [0|255] ""  PC,SBMU
 SG_ M2P_NUM_OF_SBMU : 56|8@1+ (1,0) [0|255] ""  PC

BO_ 2332225193 M2P_SUMDATA2__25: 8 MBMU
 SG_ M2P_LifeSignal_25 : 0|4@1+ (1,0) [0|15] ""  PC,SBMU
 SG_ M2P_ST_Power_25 : 4|1@1+ (1,0) [0|1] ""  PC,SBMU
 SG_ M2P_ST_Master_slave_25 : 5|1@1+ (1,0) [0|1] ""  PC,SBMU
 SG_ M2P_Status_Fan_SW_25 : 7|1@1+ (1,0) [0|1] ""  PC,SBMU
 SG_ M2P_Circuit_Breaker_25 : 8|16@1+ (1,0) [0|65535] ""  PC,SBMU
 SG_ M2P_NUM_OF_SlaveMBMU : 24|4@1+ (1,0) [0|15] ""  PC,SBMU
 SG_ M2P_RackInhabitResult : 28|2@1+ (1,0) [0|3] ""  PC,SBMU
 SG_ M2P_STofSBMUAutoCoding_25 : 30|2@1+ (1,0) [0|3] ""  PC,SBMU
 SG_ M2P_LvSelfLock : 32|1@1+ (1,0) [0|1] ""  PC,SBMU
 SG_ M2P_SbmuPwrOnFlg : 33|1@1+ (1,0) [0|1] ""  PC,SBMU
 SG_ M2P_InsulPwrOnFlg : 34|1@1+ (1,0) [0|1] ""  PC,SBMU
 SG_ M2P_HvOffReqFlg : 35|1@1+ (1,0) [0|1] ""  PC,SBMU
 SG_ M2P_HvOnAllowFlg : 36|1@1+ (1,0) [0|1] ""  PC,SBMU
 SG_ M2P_SBMULvoffAbnomal : 37|1@1+ (1,0) [0|1] ""  PC,SBMU
 SG_ M2P_LVPwrDFaultR : 38|2@1+ (1,0) [0|3] ""  PC,SBMU
 SG_ M2P_SysRunState : 40|3@1+ (1,0) [0|7] ""  PC,SBMU
 SG_ M2P_MIN_NUM_OF_ONLINE_SBMU : 43|5@1+ (1,0) [0|31] ""  PC,SBMU
 SG_ MBMU_Tank_Num_RelayOn : 48|8@1+ (1,0) [0|255] ""  PC,SBMU
 SG_ M2P_NUM_OF_SBMU : 56|8@1+ (1,0) [0|255] ""  PC

BO_ 2332225194 M2P_SUMDATA2__26: 8 MBMU
 SG_ M2P_LifeSignal_26 : 0|4@1+ (1,0) [0|15] ""  PC,SBMU
 SG_ M2P_ST_Power_26 : 4|1@1+ (1,0) [0|1] ""  PC,SBMU
 SG_ M2P_ST_Master_slave_26 : 5|1@1+ (1,0) [0|1] ""  PC,SBMU
 SG_ M2P_Status_Fan_SW_26 : 7|1@1+ (1,0) [0|1] ""  PC,SBMU
 SG_ M2P_Circuit_Breaker_26 : 8|16@1+ (1,0) [0|65535] ""  PC,SBMU
 SG_ M2P_NUM_OF_SlaveMBMU : 24|4@1+ (1,0) [0|15] ""  PC,SBMU
 SG_ M2P_RackInhabitResult : 28|2@1+ (1,0) [0|3] ""  PC,SBMU
 SG_ M2P_STofSBMUAutoCoding_26 : 30|2@1+ (1,0) [0|3] ""  PC,SBMU
 SG_ M2P_LvSelfLock : 32|1@1+ (1,0) [0|1] ""  PC,SBMU
 SG_ M2P_SbmuPwrOnFlg : 33|1@1+ (1,0) [0|1] ""  PC,SBMU
 SG_ M2P_InsulPwrOnFlg : 34|1@1+ (1,0) [0|1] ""  PC,SBMU
 SG_ M2P_HvOffReqFlg : 35|1@1+ (1,0) [0|1] ""  PC,SBMU
 SG_ M2P_HvOnAllowFlg : 36|1@1+ (1,0) [0|1] ""  PC,SBMU
 SG_ M2P_SBMULvoffAbnomal : 37|1@1+ (1,0) [0|1] ""  PC,SBMU
 SG_ M2P_LVPwrDFaultR : 38|2@1+ (1,0) [0|3] ""  PC,SBMU
 SG_ M2P_SysRunState : 40|3@1+ (1,0) [0|7] ""  PC,SBMU
 SG_ M2P_MIN_NUM_OF_ONLINE_SBMU : 43|5@1+ (1,0) [0|31] ""  PC,SBMU
 SG_ MBMU_Tank_Num_RelayOn : 48|8@1+ (1,0) [0|255] ""  PC,SBMU
 SG_ M2P_NUM_OF_SBMU : 56|8@1+ (1,0) [0|255] ""  PC

BO_ 2332225195 M2P_SUMDATA2__27: 8 MBMU
 SG_ M2P_LifeSignal_27 : 0|4@1+ (1,0) [0|15] ""  PC,SBMU
 SG_ M2P_ST_Power_27 : 4|1@1+ (1,0) [0|1] ""  PC,SBMU
 SG_ M2P_ST_Master_slave_27 : 5|1@1+ (1,0) [0|1] ""  PC,SBMU
 SG_ M2P_Status_Fan_SW_27 : 7|1@1+ (1,0) [0|1] ""  PC,SBMU
 SG_ M2P_Circuit_Breaker_27 : 8|16@1+ (1,0) [0|65535] ""  PC,SBMU
 SG_ M2P_NUM_OF_SlaveMBMU : 24|4@1+ (1,0) [0|15] ""  PC,SBMU
 SG_ M2P_RackInhabitResult : 28|2@1+ (1,0) [0|3] ""  PC,SBMU
 SG_ M2P_STofSBMUAutoCoding_27 : 30|2@1+ (1,0) [0|3] ""  PC,SBMU
 SG_ M2P_LvSelfLock : 32|1@1+ (1,0) [0|1] ""  PC,SBMU
 SG_ M2P_SbmuPwrOnFlg : 33|1@1+ (1,0) [0|1] ""  PC,SBMU
 SG_ M2P_InsulPwrOnFlg : 34|1@1+ (1,0) [0|1] ""  PC,SBMU
 SG_ M2P_HvOffReqFlg : 35|1@1+ (1,0) [0|1] ""  PC,SBMU
 SG_ M2P_HvOnAllowFlg : 36|1@1+ (1,0) [0|1] ""  PC,SBMU
 SG_ M2P_SBMULvoffAbnomal : 37|1@1+ (1,0) [0|1] ""  PC,SBMU
 SG_ M2P_LVPwrDFaultR : 38|2@1+ (1,0) [0|3] ""  PC,SBMU
 SG_ M2P_SysRunState : 40|3@1+ (1,0) [0|7] ""  PC,SBMU
 SG_ M2P_MIN_NUM_OF_ONLINE_SBMU : 43|5@1+ (1,0) [0|31] ""  PC,SBMU
 SG_ MBMU_Tank_Num_RelayOn : 48|8@1+ (1,0) [0|255] ""  PC,SBMU
 SG_ M2P_NUM_OF_SBMU : 56|8@1+ (1,0) [0|255] ""  PC

BO_ 2332225196 M2P_SUMDATA2__28: 8 MBMU
 SG_ M2P_LifeSignal_28 : 0|4@1+ (1,0) [0|15] ""  PC,SBMU
 SG_ M2P_ST_Power_28 : 4|1@1+ (1,0) [0|1] ""  PC,SBMU
 SG_ M2P_ST_Master_slave_28 : 5|1@1+ (1,0) [0|1] ""  PC,SBMU
 SG_ M2P_Status_Fan_SW_28 : 7|1@1+ (1,0) [0|1] ""  PC,SBMU
 SG_ M2P_Circuit_Breaker_28 : 8|16@1+ (1,0) [0|65535] ""  PC,SBMU
 SG_ M2P_NUM_OF_SlaveMBMU : 24|4@1+ (1,0) [0|15] ""  PC,SBMU
 SG_ M2P_RackInhabitResult : 28|2@1+ (1,0) [0|3] ""  PC,SBMU
 SG_ M2P_STofSBMUAutoCoding_28 : 30|2@1+ (1,0) [0|3] ""  PC,SBMU
 SG_ M2P_LvSelfLock : 32|1@1+ (1,0) [0|1] ""  PC,SBMU
 SG_ M2P_SbmuPwrOnFlg : 33|1@1+ (1,0) [0|1] ""  PC,SBMU
 SG_ M2P_InsulPwrOnFlg : 34|1@1+ (1,0) [0|1] ""  PC,SBMU
 SG_ M2P_HvOffReqFlg : 35|1@1+ (1,0) [0|1] ""  PC,SBMU
 SG_ M2P_HvOnAllowFlg : 36|1@1+ (1,0) [0|1] ""  PC,SBMU
 SG_ M2P_SBMULvoffAbnomal : 37|1@1+ (1,0) [0|1] ""  PC,SBMU
 SG_ M2P_LVPwrDFaultR : 38|2@1+ (1,0) [0|3] ""  PC,SBMU
 SG_ M2P_SysRunState : 40|3@1+ (1,0) [0|7] ""  PC,SBMU
 SG_ M2P_MIN_NUM_OF_ONLINE_SBMU : 43|5@1+ (1,0) [0|31] ""  PC,SBMU
 SG_ MBMU_Tank_Num_RelayOn : 48|8@1+ (1,0) [0|255] ""  PC,SBMU
 SG_ M2P_NUM_OF_SBMU : 56|8@1+ (1,0) [0|255] ""  PC

BO_ 2332225197 M2P_SUMDATA2__29: 8 MBMU
 SG_ M2P_LifeSignal_29 : 0|4@1+ (1,0) [0|15] ""  PC,SBMU
 SG_ M2P_ST_Power_29 : 4|1@1+ (1,0) [0|1] ""  PC,SBMU
 SG_ M2P_ST_Master_slave_29 : 5|1@1+ (1,0) [0|1] ""  PC,SBMU
 SG_ M2P_Status_Fan_SW_29 : 7|1@1+ (1,0) [0|1] ""  PC,SBMU
 SG_ M2P_Circuit_Breaker_29 : 8|16@1+ (1,0) [0|65535] ""  PC,SBMU
 SG_ M2P_NUM_OF_SlaveMBMU : 24|4@1+ (1,0) [0|15] ""  PC,SBMU
 SG_ M2P_RackInhabitResult : 28|2@1+ (1,0) [0|3] ""  PC,SBMU
 SG_ M2P_STofSBMUAutoCoding_29 : 30|2@1+ (1,0) [0|3] ""  PC,SBMU
 SG_ M2P_LvSelfLock : 32|1@1+ (1,0) [0|1] ""  PC,SBMU
 SG_ M2P_SbmuPwrOnFlg : 33|1@1+ (1,0) [0|1] ""  PC,SBMU
 SG_ M2P_InsulPwrOnFlg : 34|1@1+ (1,0) [0|1] ""  PC,SBMU
 SG_ M2P_HvOffReqFlg : 35|1@1+ (1,0) [0|1] ""  PC,SBMU
 SG_ M2P_HvOnAllowFlg : 36|1@1+ (1,0) [0|1] ""  PC,SBMU
 SG_ M2P_SBMULvoffAbnomal : 37|1@1+ (1,0) [0|1] ""  PC,SBMU
 SG_ M2P_LVPwrDFaultR : 38|2@1+ (1,0) [0|3] ""  PC,SBMU
 SG_ M2P_SysRunState : 40|3@1+ (1,0) [0|7] ""  PC,SBMU
 SG_ M2P_MIN_NUM_OF_ONLINE_SBMU : 43|5@1+ (1,0) [0|31] ""  PC,SBMU
 SG_ MBMU_Tank_Num_RelayOn : 48|8@1+ (1,0) [0|255] ""  PC,SBMU
 SG_ M2P_NUM_OF_SBMU : 56|8@1+ (1,0) [0|255] ""  PC

BO_ 2332225198 M2P_SUMDATA2__30: 8 MBMU
 SG_ M2P_LifeSignal_30 : 0|4@1+ (1,0) [0|15] ""  PC,SBMU
 SG_ M2P_ST_Power_30 : 4|1@1+ (1,0) [0|1] ""  PC,SBMU
 SG_ M2P_ST_Master_slave_30 : 5|1@1+ (1,0) [0|1] ""  PC,SBMU
 SG_ M2P_Status_Fan_SW_30 : 7|1@1+ (1,0) [0|1] ""  PC,SBMU
 SG_ M2P_Circuit_Breaker_30 : 8|16@1+ (1,0) [0|65535] ""  PC,SBMU
 SG_ M2P_NUM_OF_SlaveMBMU : 24|4@1+ (1,0) [0|15] ""  PC,SBMU
 SG_ M2P_RackInhabitResult : 28|2@1+ (1,0) [0|3] ""  PC,SBMU
 SG_ M2P_STofSBMUAutoCoding_30 : 30|2@1+ (1,0) [0|3] ""  PC,SBMU
 SG_ M2P_LvSelfLock : 32|1@1+ (1,0) [0|1] ""  PC,SBMU
 SG_ M2P_SbmuPwrOnFlg : 33|1@1+ (1,0) [0|1] ""  PC,SBMU
 SG_ M2P_InsulPwrOnFlg : 34|1@1+ (1,0) [0|1] ""  PC,SBMU
 SG_ M2P_HvOffReqFlg : 35|1@1+ (1,0) [0|1] ""  PC,SBMU
 SG_ M2P_HvOnAllowFlg : 36|1@1+ (1,0) [0|1] ""  PC,SBMU
 SG_ M2P_SBMULvoffAbnomal : 37|1@1+ (1,0) [0|1] ""  PC,SBMU
 SG_ M2P_LVPwrDFaultR : 38|2@1+ (1,0) [0|3] ""  PC,SBMU
 SG_ M2P_SysRunState : 40|3@1+ (1,0) [0|7] ""  PC,SBMU
 SG_ M2P_MIN_NUM_OF_ONLINE_SBMU : 43|5@1+ (1,0) [0|31] ""  PC,SBMU
 SG_ MBMU_Tank_Num_RelayOn : 48|8@1+ (1,0) [0|255] ""  PC,SBMU
 SG_ M2P_NUM_OF_SBMU : 56|8@1+ (1,0) [0|255] ""  PC

BO_ 2332225199 M2P_SUMDATA2__31: 8 MBMU
 SG_ M2P_LifeSignal_31 : 0|4@1+ (1,0) [0|15] ""  PC,SBMU
 SG_ M2P_ST_Power_31 : 4|1@1+ (1,0) [0|1] ""  PC,SBMU
 SG_ M2P_ST_Master_slave_31 : 5|1@1+ (1,0) [0|1] ""  PC,SBMU
 SG_ M2P_Status_Fan_SW_31 : 7|1@1+ (1,0) [0|1] ""  PC,SBMU
 SG_ M2P_Circuit_Breaker_31 : 8|16@1+ (1,0) [0|65535] ""  PC,SBMU
 SG_ M2P_NUM_OF_SlaveMBMU : 24|4@1+ (1,0) [0|15] ""  PC,SBMU
 SG_ M2P_RackInhabitResult : 28|2@1+ (1,0) [0|3] ""  PC,SBMU
 SG_ M2P_STofSBMUAutoCoding_31 : 30|2@1+ (1,0) [0|3] ""  PC,SBMU
 SG_ M2P_LvSelfLock : 32|1@1+ (1,0) [0|1] ""  PC,SBMU
 SG_ M2P_SbmuPwrOnFlg : 33|1@1+ (1,0) [0|1] ""  PC,SBMU
 SG_ M2P_InsulPwrOnFlg : 34|1@1+ (1,0) [0|1] ""  PC,SBMU
 SG_ M2P_HvOffReqFlg : 35|1@1+ (1,0) [0|1] ""  PC,SBMU
 SG_ M2P_HvOnAllowFlg : 36|1@1+ (1,0) [0|1] ""  PC,SBMU
 SG_ M2P_SBMULvoffAbnomal : 37|1@1+ (1,0) [0|1] ""  PC,SBMU
 SG_ M2P_LVPwrDFaultR : 38|2@1+ (1,0) [0|3] ""  PC,SBMU
 SG_ M2P_SysRunState : 40|3@1+ (1,0) [0|7] ""  PC,SBMU
 SG_ M2P_MIN_NUM_OF_ONLINE_SBMU : 43|5@1+ (1,0) [0|31] ""  PC,SBMU
 SG_ MBMU_Tank_Num_RelayOn : 48|8@1+ (1,0) [0|255] ""  PC,SBMU
 SG_ M2P_NUM_OF_SBMU : 56|8@1+ (1,0) [0|255] ""  PC

BO_ 2332290705 M2P_SUMDATA3__01: 8 MBMU
 SG_ M2P_PermitMaxCharge_I_01 : 0|16@1+ (1,-20000) [-20000|45535] "A"  PC
 SG_ M2P_PermitMaxDisCharge_I_01 : 16|16@1+ (1,-20000) [-20000|45535] "A"  PC
 SG_ M2P_Evn_T1_01 : 32|8@1+ (1,-50) [-50|205] "℃"  PC
 SG_ M2P_Evn_T2_01 : 40|8@1+ (1,-50) [-50|205] "℃"  PC
 SG_ M2P_Evn_T3_01 : 48|8@1+ (1,-50) [-50|205] "℃"  PC
 SG_ M2P_Evn_Humidity_01 : 56|8@1+ (1,0) [0|255] "%"  PC

BO_ 2332290706 M2P_SUMDATA3__02: 8 MBMU
 SG_ M2P_PermitMaxCharge_I_02 : 0|16@1+ (1,-20000) [-20000|45535] "A"  PC
 SG_ M2P_PermitMaxDisCharge_I_02 : 16|16@1+ (1,-20000) [-20000|45535] "A"  PC
 SG_ M2P_Evn_T1_02 : 32|8@1+ (1,-50) [-50|205] "℃"  PC
 SG_ M2P_Evn_T2_02 : 40|8@1+ (1,-50) [-50|205] "℃"  PC
 SG_ M2P_Evn_T3_02 : 48|8@1+ (1,-50) [-50|205] "℃"  PC
 SG_ M2P_Evn_Humidity_02 : 56|8@1+ (1,0) [0|255] "%"  PC

BO_ 2332290707 M2P_SUMDATA3__03: 8 MBMU
 SG_ M2P_PermitMaxCharge_I_03 : 0|16@1+ (1,-20000) [-20000|45535] "A"  PC
 SG_ M2P_PermitMaxDisCharge_I_03 : 16|16@1+ (1,-20000) [-20000|45535] "A"  PC
 SG_ M2P_Evn_T1_03 : 32|8@1+ (1,-50) [-50|205] "℃"  PC
 SG_ M2P_Evn_T2_03 : 40|8@1+ (1,-50) [-50|205] "℃"  PC
 SG_ M2P_Evn_T3_03 : 48|8@1+ (1,-50) [-50|205] "℃"  PC
 SG_ M2P_Evn_Humidity_03 : 56|8@1+ (1,0) [0|255] "%"  PC

BO_ 2332290708 M2P_SUMDATA3__04: 8 MBMU
 SG_ M2P_PermitMaxCharge_I_04 : 0|16@1+ (1,-20000) [-20000|45535] "A"  PC
 SG_ M2P_PermitMaxDisCharge_I_04 : 16|16@1+ (1,-20000) [-20000|45535] "A"  PC
 SG_ M2P_Evn_T1_04 : 32|8@1+ (1,-50) [-50|205] "℃"  PC
 SG_ M2P_Evn_T2_04 : 40|8@1+ (1,-50) [-50|205] "℃"  PC
 SG_ M2P_Evn_T3_04 : 48|8@1+ (1,-50) [-50|205] "℃"  PC
 SG_ M2P_Evn_Humidity_04 : 56|8@1+ (1,0) [0|255] "%"  PC

BO_ 2332290709 M2P_SUMDATA3__05: 8 MBMU
 SG_ M2P_PermitMaxCharge_I_05 : 0|16@1+ (1,-20000) [-20000|45535] "A"  PC
 SG_ M2P_PermitMaxDisCharge_I_05 : 16|16@1+ (1,-20000) [-20000|45535] "A"  PC
 SG_ M2P_Evn_T1_05 : 32|8@1+ (1,-50) [-50|205] "℃"  PC
 SG_ M2P_Evn_T2_05 : 40|8@1+ (1,-50) [-50|205] "℃"  PC
 SG_ M2P_Evn_T3_05 : 48|8@1+ (1,-50) [-50|205] "℃"  PC
 SG_ M2P_Evn_Humidity_05 : 56|8@1+ (1,0) [0|255] "%"  PC

BO_ 2332290710 M2P_SUMDATA3__06: 8 MBMU
 SG_ M2P_PermitMaxCharge_I_06 : 0|16@1+ (1,-20000) [-20000|45535] "A"  PC
 SG_ M2P_PermitMaxDisCharge_I_06 : 16|16@1+ (1,-20000) [-20000|45535] "A"  PC
 SG_ M2P_Evn_T1_06 : 32|8@1+ (1,-50) [-50|205] "℃"  PC
 SG_ M2P_Evn_T2_06 : 40|8@1+ (1,-50) [-50|205] "℃"  PC
 SG_ M2P_Evn_T3_06 : 48|8@1+ (1,-50) [-50|205] "℃"  PC
 SG_ M2P_Evn_Humidity_06 : 56|8@1+ (1,0) [0|255] "%"  PC

BO_ 2332290711 M2P_SUMDATA3__07: 8 MBMU
 SG_ M2P_PermitMaxCharge_I_07 : 0|16@1+ (1,-20000) [-20000|45535] "A"  PC
 SG_ M2P_PermitMaxDisCharge_I_07 : 16|16@1+ (1,-20000) [-20000|45535] "A"  PC
 SG_ M2P_Evn_T1_07 : 32|8@1+ (1,-50) [-50|205] "℃"  PC
 SG_ M2P_Evn_T2_07 : 40|8@1+ (1,-50) [-50|205] "℃"  PC
 SG_ M2P_Evn_T3_07 : 48|8@1+ (1,-50) [-50|205] "℃"  PC
 SG_ M2P_Evn_Humidity_07 : 56|8@1+ (1,0) [0|255] "%"  PC

BO_ 2332290712 M2P_SUMDATA3__08: 8 MBMU
 SG_ M2P_PermitMaxCharge_I_08 : 0|16@1+ (1,-20000) [-20000|45535] "A"  PC
 SG_ M2P_PermitMaxDisCharge_I_08 : 16|16@1+ (1,-20000) [-20000|45535] "A"  PC
 SG_ M2P_Evn_T1_08 : 32|8@1+ (1,-50) [-50|205] "℃"  PC
 SG_ M2P_Evn_T2_08 : 40|8@1+ (1,-50) [-50|205] "℃"  PC
 SG_ M2P_Evn_T3_08 : 48|8@1+ (1,-50) [-50|205] "℃"  PC
 SG_ M2P_Evn_Humidity_08 : 56|8@1+ (1,0) [0|255] "%"  PC

BO_ 2332290713 M2P_SUMDATA3__09: 8 MBMU
 SG_ M2P_PermitMaxCharge_I_09 : 0|16@1+ (1,-20000) [-20000|45535] "A"  PC
 SG_ M2P_PermitMaxDisCharge_I_09 : 16|16@1+ (1,-20000) [-20000|45535] "A"  PC
 SG_ M2P_Evn_T1_09 : 32|8@1+ (1,-50) [-50|205] "℃"  PC
 SG_ M2P_Evn_T2_09 : 40|8@1+ (1,-50) [-50|205] "℃"  PC
 SG_ M2P_Evn_T3_09 : 48|8@1+ (1,-50) [-50|205] "℃"  PC
 SG_ M2P_Evn_Humidity_09 : 56|8@1+ (1,0) [0|255] "%"  PC

BO_ 2332290714 M2P_SUMDATA3__10: 8 MBMU
 SG_ M2P_PermitMaxCharge_I_10 : 0|16@1+ (1,-20000) [-20000|45535] "A"  PC
 SG_ M2P_PermitMaxDisCharge_I_10 : 16|16@1+ (1,-20000) [-20000|45535] "A"  PC
 SG_ M2P_Evn_T1_10 : 32|8@1+ (1,-50) [-50|205] "℃"  PC
 SG_ M2P_Evn_T2_10 : 40|8@1+ (1,-50) [-50|205] "℃"  PC
 SG_ M2P_Evn_T3_10 : 48|8@1+ (1,-50) [-50|205] "℃"  PC
 SG_ M2P_Evn_Humidity_10 : 56|8@1+ (1,0) [0|255] "%"  PC

BO_ 2332290715 M2P_SUMDATA3__11: 8 MBMU
 SG_ M2P_PermitMaxCharge_I_11 : 0|16@1+ (1,-20000) [-20000|45535] "A"  PC
 SG_ M2P_PermitMaxDisCharge_I_11 : 16|16@1+ (1,-20000) [-20000|45535] "A"  PC
 SG_ M2P_Evn_T1_11 : 32|8@1+ (1,-50) [-50|205] "℃"  PC
 SG_ M2P_Evn_T2_11 : 40|8@1+ (1,-50) [-50|205] "℃"  PC
 SG_ M2P_Evn_T3_11 : 48|8@1+ (1,-50) [-50|205] "℃"  PC
 SG_ M2P_Evn_Humidity_11 : 56|8@1+ (1,0) [0|255] "%"  PC

BO_ 2332290716 M2P_SUMDATA3__12: 8 MBMU
 SG_ M2P_PermitMaxCharge_I_12 : 0|16@1+ (1,-20000) [-20000|45535] "A"  PC
 SG_ M2P_PermitMaxDisCharge_I_12 : 16|16@1+ (1,-20000) [-20000|45535] "A"  PC
 SG_ M2P_Evn_T1_12 : 32|8@1+ (1,-50) [-50|205] "℃"  PC
 SG_ M2P_Evn_T2_12 : 40|8@1+ (1,-50) [-50|205] "℃"  PC
 SG_ M2P_Evn_T3_12 : 48|8@1+ (1,-50) [-50|205] "℃"  PC
 SG_ M2P_Evn_Humidity_12 : 56|8@1+ (1,0) [0|255] "%"  PC

BO_ 2332290717 M2P_SUMDATA3__13: 8 MBMU
 SG_ M2P_PermitMaxCharge_I_13 : 0|16@1+ (1,-20000) [-20000|45535] "A"  PC
 SG_ M2P_PermitMaxDisCharge_I_13 : 16|16@1+ (1,-20000) [-20000|45535] "A"  PC
 SG_ M2P_Evn_T1_13 : 32|8@1+ (1,-50) [-50|205] "℃"  PC
 SG_ M2P_Evn_T2_13 : 40|8@1+ (1,-50) [-50|205] "℃"  PC
 SG_ M2P_Evn_T3_13 : 48|8@1+ (1,-50) [-50|205] "℃"  PC
 SG_ M2P_Evn_Humidity_13 : 56|8@1+ (1,0) [0|255] "%"  PC

BO_ 2332290718 M2P_SUMDATA3__14: 8 MBMU
 SG_ M2P_PermitMaxCharge_I_14 : 0|16@1+ (1,-20000) [-20000|45535] "A"  PC
 SG_ M2P_PermitMaxDisCharge_I_14 : 16|16@1+ (1,-20000) [-20000|45535] "A"  PC
 SG_ M2P_Evn_T1_14 : 32|8@1+ (1,-50) [-50|205] "℃"  PC
 SG_ M2P_Evn_T2_14 : 40|8@1+ (1,-50) [-50|205] "℃"  PC
 SG_ M2P_Evn_T3_14 : 48|8@1+ (1,-50) [-50|205] "℃"  PC
 SG_ M2P_Evn_Humidity_14 : 56|8@1+ (1,0) [0|255] "%"  PC

BO_ 2332290719 M2P_SUMDATA3__15: 8 MBMU
 SG_ M2P_PermitMaxCharge_I_15 : 0|16@1+ (1,-20000) [-20000|45535] "A"  PC
 SG_ M2P_PermitMaxDisCharge_I_15 : 16|16@1+ (1,-20000) [-20000|45535] "A"  PC
 SG_ M2P_Evn_T1_15 : 32|8@1+ (1,-50) [-50|205] "℃"  PC
 SG_ M2P_Evn_T2_15 : 40|8@1+ (1,-50) [-50|205] "℃"  PC
 SG_ M2P_Evn_T3_15 : 48|8@1+ (1,-50) [-50|205] "℃"  PC
 SG_ M2P_Evn_Humidity_15 : 56|8@1+ (1,0) [0|255] "%"  PC

BO_ 2332290720 M2P_SUMDATA3__16: 8 MBMU
 SG_ M2P_PermitMaxCharge_I_16 : 0|16@1+ (1,-20000) [-20000|45535] "A"  PC
 SG_ M2P_PermitMaxDisCharge_I_16 : 16|16@1+ (1,-20000) [-20000|45535] "A"  PC
 SG_ M2P_Evn_T1_16 : 32|8@1+ (1,-50) [-50|205] "℃"  PC
 SG_ M2P_Evn_T2_16 : 40|8@1+ (1,-50) [-50|205] "℃"  PC
 SG_ M2P_Evn_T3_16 : 48|8@1+ (1,-50) [-50|205] "℃"  PC
 SG_ M2P_Evn_Humidity_16 : 56|8@1+ (1,0) [0|255] "%"  PC

BO_ 2332290721 M2P_SUMDATA3__17: 8 MBMU
 SG_ M2P_PermitMaxCharge_I_17 : 0|16@1+ (1,-20000) [-20000|45535] "A"  PC
 SG_ M2P_PermitMaxDisCharge_I_17 : 16|16@1+ (1,-20000) [-20000|45535] "A"  PC
 SG_ M2P_Evn_T1_17 : 32|8@1+ (1,-50) [-50|205] "℃"  PC
 SG_ M2P_Evn_T2_17 : 40|8@1+ (1,-50) [-50|205] "℃"  PC
 SG_ M2P_Evn_T3_17 : 48|8@1+ (1,-50) [-50|205] "℃"  PC
 SG_ M2P_Evn_Humidity_17 : 56|8@1+ (1,0) [0|255] "%"  PC

BO_ 2332290722 M2P_SUMDATA3__18: 8 MBMU
 SG_ M2P_PermitMaxCharge_I_18 : 0|16@1+ (1,-20000) [-20000|45535] "A"  PC
 SG_ M2P_PermitMaxDisCharge_I_18 : 16|16@1+ (1,-20000) [-20000|45535] "A"  PC
 SG_ M2P_Evn_T1_18 : 32|8@1+ (1,-50) [-50|205] "℃"  PC
 SG_ M2P_Evn_T2_18 : 40|8@1+ (1,-50) [-50|205] "℃"  PC
 SG_ M2P_Evn_T3_18 : 48|8@1+ (1,-50) [-50|205] "℃"  PC
 SG_ M2P_Evn_Humidity_18 : 56|8@1+ (1,0) [0|255] "%"  PC

BO_ 2332290723 M2P_SUMDATA3__19: 8 MBMU
 SG_ M2P_PermitMaxCharge_I_19 : 0|16@1+ (1,-20000) [-20000|45535] "A"  PC
 SG_ M2P_PermitMaxDisCharge_I_19 : 16|16@1+ (1,-20000) [-20000|45535] "A"  PC
 SG_ M2P_Evn_T1_19 : 32|8@1+ (1,-50) [-50|205] "℃"  PC
 SG_ M2P_Evn_T2_19 : 40|8@1+ (1,-50) [-50|205] "℃"  PC
 SG_ M2P_Evn_T3_19 : 48|8@1+ (1,-50) [-50|205] "℃"  PC
 SG_ M2P_Evn_Humidity_19 : 56|8@1+ (1,0) [0|255] "%"  PC

BO_ 2332290724 M2P_SUMDATA3__20: 8 MBMU
 SG_ M2P_PermitMaxCharge_I_20 : 0|16@1+ (1,-20000) [-20000|45535] "A"  PC
 SG_ M2P_PermitMaxDisCharge_I_20 : 16|16@1+ (1,-20000) [-20000|45535] "A"  PC
 SG_ M2P_Evn_T1_20 : 32|8@1+ (1,-50) [-50|205] "℃"  PC
 SG_ M2P_Evn_T2_20 : 40|8@1+ (1,-50) [-50|205] "℃"  PC
 SG_ M2P_Evn_T3_20 : 48|8@1+ (1,-50) [-50|205] "℃"  PC
 SG_ M2P_Evn_Humidity_20 : 56|8@1+ (1,0) [0|255] "%"  PC

BO_ 2332290725 M2P_SUMDATA3__21: 8 MBMU
 SG_ M2P_PermitMaxCharge_I_21 : 0|16@1+ (1,-20000) [-20000|45535] "A"  PC
 SG_ M2P_PermitMaxDisCharge_I_21 : 16|16@1+ (1,-20000) [-20000|45535] "A"  PC
 SG_ M2P_Evn_T1_21 : 32|8@1+ (1,-50) [-50|205] "℃"  PC
 SG_ M2P_Evn_T2_21 : 40|8@1+ (1,-50) [-50|205] "℃"  PC
 SG_ M2P_Evn_T3_21 : 48|8@1+ (1,-50) [-50|205] "℃"  PC
 SG_ M2P_Evn_Humidity_21 : 56|8@1+ (1,0) [0|255] "%"  PC

BO_ 2332290726 M2P_SUMDATA3__22: 8 MBMU
 SG_ M2P_PermitMaxCharge_I_22 : 0|16@1+ (1,-20000) [-20000|45535] "A"  PC
 SG_ M2P_PermitMaxDisCharge_I_22 : 16|16@1+ (1,-20000) [-20000|45535] "A"  PC
 SG_ M2P_Evn_T1_22 : 32|8@1+ (1,-50) [-50|205] "℃"  PC
 SG_ M2P_Evn_T2_22 : 40|8@1+ (1,-50) [-50|205] "℃"  PC
 SG_ M2P_Evn_T3_22 : 48|8@1+ (1,-50) [-50|205] "℃"  PC
 SG_ M2P_Evn_Humidity_22 : 56|8@1+ (1,0) [0|255] "%"  PC

BO_ 2332290727 M2P_SUMDATA3__23: 8 MBMU
 SG_ M2P_PermitMaxCharge_I_23 : 0|16@1+ (1,-20000) [-20000|45535] "A"  PC
 SG_ M2P_PermitMaxDisCharge_I_23 : 16|16@1+ (1,-20000) [-20000|45535] "A"  PC
 SG_ M2P_Evn_T1_23 : 32|8@1+ (1,-50) [-50|205] "℃"  PC
 SG_ M2P_Evn_T2_23 : 40|8@1+ (1,-50) [-50|205] "℃"  PC
 SG_ M2P_Evn_T3_23 : 48|8@1+ (1,-50) [-50|205] "℃"  PC
 SG_ M2P_Evn_Humidity_23 : 56|8@1+ (1,0) [0|255] "%"  PC

BO_ 2332290728 M2P_SUMDATA3__24: 8 MBMU
 SG_ M2P_PermitMaxCharge_I_24 : 0|16@1+ (1,-20000) [-20000|45535] "A"  PC
 SG_ M2P_PermitMaxDisCharge_I_24 : 16|16@1+ (1,-20000) [-20000|45535] "A"  PC
 SG_ M2P_Evn_T1_24 : 32|8@1+ (1,-50) [-50|205] "℃"  PC
 SG_ M2P_Evn_T2_24 : 40|8@1+ (1,-50) [-50|205] "℃"  PC
 SG_ M2P_Evn_T3_24 : 48|8@1+ (1,-50) [-50|205] "℃"  PC
 SG_ M2P_Evn_Humidity_24 : 56|8@1+ (1,0) [0|255] "%"  PC

BO_ 2332290729 M2P_SUMDATA3__25: 8 MBMU
 SG_ M2P_PermitMaxCharge_I_25 : 0|16@1+ (1,-20000) [-20000|45535] "A"  PC
 SG_ M2P_PermitMaxDisCharge_I_25 : 16|16@1+ (1,-20000) [-20000|45535] "A"  PC
 SG_ M2P_Evn_T1_25 : 32|8@1+ (1,-50) [-50|205] "℃"  PC
 SG_ M2P_Evn_T2_25 : 40|8@1+ (1,-50) [-50|205] "℃"  PC
 SG_ M2P_Evn_T3_25 : 48|8@1+ (1,-50) [-50|205] "℃"  PC
 SG_ M2P_Evn_Humidity_25 : 56|8@1+ (1,0) [0|255] "%"  PC

BO_ 2332290730 M2P_SUMDATA3__26: 8 MBMU
 SG_ M2P_PermitMaxCharge_I_26 : 0|16@1+ (1,-20000) [-20000|45535] "A"  PC
 SG_ M2P_PermitMaxDisCharge_I_26 : 16|16@1+ (1,-20000) [-20000|45535] "A"  PC
 SG_ M2P_Evn_T1_26 : 32|8@1+ (1,-50) [-50|205] "℃"  PC
 SG_ M2P_Evn_T2_26 : 40|8@1+ (1,-50) [-50|205] "℃"  PC
 SG_ M2P_Evn_T3_26 : 48|8@1+ (1,-50) [-50|205] "℃"  PC
 SG_ M2P_Evn_Humidity_26 : 56|8@1+ (1,0) [0|255] "%"  PC

CM_ SG_ 2265050781 M2P_AL_Fault_Page_13 "故障码页";
CM_ SG_ 2265050781 M2P_AL_Fault_Number1_13 "故障码1";
CM_ SG_ 2265050781 M2P_AL_Fault_Number2_13 "故障码2";
CM_ SG_ 2265050781 M2P_AL_Fault_Number3_13 "故障码3";
CM_ SG_ 2265050781 M2P_AL_Fault_Number4_13 "故障码4";
CM_ SG_ 2265050781 M2P_AL_Fault_Number5_13 "故障码5";
CM_ SG_ 2265050781 M2P_AL_Fault_Number6_13 "故障码6";
CM_ SG_ 2265050782 M2P_AL_Fault_Page_14 "故障码页";
CM_ SG_ 2265050782 M2P_AL_Fault_Number1_14 "故障码1";
CM_ SG_ 2265050782 M2P_AL_Fault_Number2_14 "故障码2";
CM_ SG_ 2265050782 M2P_AL_Fault_Number3_14 "故障码3";
CM_ SG_ 2265050782 M2P_AL_Fault_Number4_14 "故障码4";
CM_ SG_ 2265050782 M2P_AL_Fault_Number5_14 "故障码5";
CM_ SG_ 2265050782 M2P_AL_Fault_Number6_14 "故障码6";
CM_ SG_ 2265050783 M2P_AL_Fault_Page_15 "故障码页";
CM_ SG_ 2265050783 M2P_AL_Fault_Number1_15 "故障码1";
CM_ SG_ 2265050783 M2P_AL_Fault_Number2_15 "故障码2";
CM_ SG_ 2265050783 M2P_AL_Fault_Number3_15 "故障码3";
CM_ SG_ 2265050783 M2P_AL_Fault_Number4_15 "故障码4";
CM_ SG_ 2265050783 M2P_AL_Fault_Number5_15 "故障码5";
CM_ SG_ 2265050783 M2P_AL_Fault_Number6_15 "故障码6";
CM_ SG_ 2265050784 M2P_AL_Fault_Page_16 "故障码页";
CM_ SG_ 2265050784 M2P_AL_Fault_Number1_16 "故障码1";
CM_ SG_ 2265050784 M2P_AL_Fault_Number2_16 "故障码2";
CM_ SG_ 2265050784 M2P_AL_Fault_Number3_16 "故障码3";
CM_ SG_ 2265050784 M2P_AL_Fault_Number4_16 "故障码4";
CM_ SG_ 2265050784 M2P_AL_Fault_Number5_16 "故障码5";
CM_ SG_ 2265050784 M2P_AL_Fault_Number6_16 "故障码6";
CM_ SG_ 2265050785 M2P_AL_Fault_Page_17 "故障码页";
CM_ SG_ 2265050785 M2P_AL_Fault_Number1_17 "故障码1";
CM_ SG_ 2265050785 M2P_AL_Fault_Number2_17 "故障码2";
CM_ SG_ 2265050785 M2P_AL_Fault_Number3_17 "故障码3";
CM_ SG_ 2265050785 M2P_AL_Fault_Number4_17 "故障码4";
CM_ SG_ 2265050785 M2P_AL_Fault_Number5_17 "故障码5";
CM_ SG_ 2265050785 M2P_AL_Fault_Number6_17 "故障码6";
CM_ SG_ 2265050786 M2P_AL_Fault_Page_18 "故障码页";
CM_ SG_ 2265050786 M2P_AL_Fault_Number1_18 "故障码1";
CM_ SG_ 2265050786 M2P_AL_Fault_Number2_18 "故障码2";
CM_ SG_ 2265050786 M2P_AL_Fault_Number3_18 "故障码3";
CM_ SG_ 2265050786 M2P_AL_Fault_Number4_18 "故障码4";
CM_ SG_ 2265050786 M2P_AL_Fault_Number5_18 "故障码5";
CM_ SG_ 2265050786 M2P_AL_Fault_Number6_18 "故障码6";
CM_ SG_ 2265050787 M2P_AL_Fault_Page_19 "故障码页";
CM_ SG_ 2265050787 M2P_AL_Fault_Number1_19 "故障码1";
CM_ SG_ 2265050787 M2P_AL_Fault_Number2_19 "故障码2";
CM_ SG_ 2265050787 M2P_AL_Fault_Number3_19 "故障码3";
CM_ SG_ 2265050787 M2P_AL_Fault_Number4_19 "故障码4";
CM_ SG_ 2265050787 M2P_AL_Fault_Number5_19 "故障码5";
CM_ SG_ 2265050787 M2P_AL_Fault_Number6_19 "故障码6";
CM_ SG_ 2265050788 M2P_AL_Fault_Page_20 "故障码页";
CM_ SG_ 2265050788 M2P_AL_Fault_Number1_20 "故障码1";
CM_ SG_ 2265050788 M2P_AL_Fault_Number2_20 "故障码2";
CM_ SG_ 2265050788 M2P_AL_Fault_Number3_20 "故障码3";
CM_ SG_ 2265050788 M2P_AL_Fault_Number4_20 "故障码4";
CM_ SG_ 2265050788 M2P_AL_Fault_Number5_20 "故障码5";
CM_ SG_ 2265050788 M2P_AL_Fault_Number6_20 "故障码6";
CM_ SG_ 2265050789 M2P_AL_Fault_Page_21 "故障码页";
CM_ SG_ 2265050789 M2P_AL_Fault_Number1_21 "故障码1";
CM_ SG_ 2265050789 M2P_AL_Fault_Number2_21 "故障码2";
CM_ SG_ 2265050789 M2P_AL_Fault_Number3_21 "故障码3";
CM_ SG_ 2265050789 M2P_AL_Fault_Number4_21 "故障码4";
CM_ SG_ 2265050789 M2P_AL_Fault_Number5_21 "故障码5";
CM_ SG_ 2265050789 M2P_AL_Fault_Number6_21 "故障码6";
CM_ SG_ 2265050790 M2P_AL_Fault_Page_22 "故障码页";
CM_ SG_ 2265050790 M2P_AL_Fault_Number1_22 "故障码1";
CM_ SG_ 2265050790 M2P_AL_Fault_Number2_22 "故障码2";
CM_ SG_ 2265050790 M2P_AL_Fault_Number3_22 "故障码3";
CM_ SG_ 2265050790 M2P_AL_Fault_Number4_22 "故障码4";
CM_ SG_ 2265050790 M2P_AL_Fault_Number5_22 "故障码5";
CM_ SG_ 2265050790 M2P_AL_Fault_Number6_22 "故障码6";
CM_ SG_ 2265050791 M2P_AL_Fault_Page_23 "故障码页";
CM_ SG_ 2265050791 M2P_AL_Fault_Number1_23 "故障码1";
CM_ SG_ 2265050791 M2P_AL_Fault_Number2_23 "故障码2";
CM_ SG_ 2265050791 M2P_AL_Fault_Number3_23 "故障码3";
CM_ SG_ 2265050791 M2P_AL_Fault_Number4_23 "故障码4";
CM_ SG_ 2265050791 M2P_AL_Fault_Number5_23 "故障码5";
CM_ SG_ 2265050791 M2P_AL_Fault_Number6_23 "故障码6";
CM_ SG_ 2265050792 M2P_AL_Fault_Page_24 "故障码页";
CM_ SG_ 2265050792 M2P_AL_Fault_Number1_24 "故障码1";
CM_ SG_ 2265050792 M2P_AL_Fault_Number2_24 "故障码2";
CM_ SG_ 2265050792 M2P_AL_Fault_Number3_24 "故障码3";
CM_ SG_ 2265050792 M2P_AL_Fault_Number4_24 "故障码4";
CM_ SG_ 2265050792 M2P_AL_Fault_Number5_24 "故障码5";
CM_ SG_ 2265050792 M2P_AL_Fault_Number6_24 "故障码6";
CM_ SG_ 2265050793 M2P_AL_Fault_Page_25 "故障码页";
CM_ SG_ 2265050793 M2P_AL_Fault_Number1_25 "故障码1";
CM_ SG_ 2265050793 M2P_AL_Fault_Number2_25 "故障码2";
CM_ SG_ 2265050793 M2P_AL_Fault_Number3_25 "故障码3";
CM_ SG_ 2265050793 M2P_AL_Fault_Number4_25 "故障码4";
CM_ SG_ 2265050793 M2P_AL_Fault_Number5_25 "故障码5";
CM_ SG_ 2265050793 M2P_AL_Fault_Number6_25 "故障码6";
CM_ SG_ 2265050794 M2P_AL_Fault_Page_26 "故障码页";
CM_ SG_ 2265050794 M2P_AL_Fault_Number1_26 "故障码1";
CM_ SG_ 2265050794 M2P_AL_Fault_Number2_26 "故障码2";
CM_ SG_ 2265050794 M2P_AL_Fault_Number3_26 "故障码3";
CM_ SG_ 2265050794 M2P_AL_Fault_Number4_26 "故障码4";
CM_ SG_ 2265050794 M2P_AL_Fault_Number5_26 "故障码5";
CM_ SG_ 2265050794 M2P_AL_Fault_Number6_26 "故障码6";
CM_ SG_ 2265050795 M2P_AL_Fault_Page_27 "故障码页";
CM_ SG_ 2265050795 M2P_AL_Fault_Number1_27 "故障码1";
CM_ SG_ 2265050795 M2P_AL_Fault_Number2_27 "故障码2";
CM_ SG_ 2265050795 M2P_AL_Fault_Number3_27 "故障码3";
CM_ SG_ 2265050795 M2P_AL_Fault_Number4_27 "故障码4";
CM_ SG_ 2265050795 M2P_AL_Fault_Number5_27 "故障码5";
CM_ SG_ 2265050795 M2P_AL_Fault_Number6_27 "故障码6";
CM_ SG_ 2265050796 M2P_AL_Fault_Page_28 "故障码页";
CM_ SG_ 2265050796 M2P_AL_Fault_Number1_28 "故障码1";
CM_ SG_ 2265050796 M2P_AL_Fault_Number2_28 "故障码2";
CM_ SG_ 2265050796 M2P_AL_Fault_Number3_28 "故障码3";
CM_ SG_ 2265050796 M2P_AL_Fault_Number4_28 "故障码4";
CM_ SG_ 2265050796 M2P_AL_Fault_Number5_28 "故障码5";
CM_ SG_ 2265050796 M2P_AL_Fault_Number6_28 "故障码6";
CM_ SG_ 2265050797 M2P_AL_Fault_Page_29 "故障码页";
CM_ SG_ 2265050797 M2P_AL_Fault_Number1_29 "故障码1";
CM_ SG_ 2265050797 M2P_AL_Fault_Number2_29 "故障码2";
CM_ SG_ 2265050797 M2P_AL_Fault_Number3_29 "故障码3";
CM_ SG_ 2265050797 M2P_AL_Fault_Number4_29 "故障码4";
CM_ SG_ 2265050797 M2P_AL_Fault_Number5_29 "故障码5";
CM_ SG_ 2265050797 M2P_AL_Fault_Number6_29 "故障码6";
CM_ SG_ 2265050798 M2P_AL_Fault_Page_30 "故障码页";
CM_ SG_ 2265050798 M2P_AL_Fault_Number1_30 "故障码1";
CM_ SG_ 2265050798 M2P_AL_Fault_Number2_30 "故障码2";
CM_ SG_ 2265050798 M2P_AL_Fault_Number3_30 "故障码3";
CM_ SG_ 2265050798 M2P_AL_Fault_Number4_30 "故障码4";
CM_ SG_ 2265050798 M2P_AL_Fault_Number5_30 "故障码5";
CM_ SG_ 2265050798 M2P_AL_Fault_Number6_30 "故障码6";
CM_ SG_ 2265050799 M2P_AL_Fault_Page_31 "故障码页";
CM_ SG_ 2265050799 M2P_AL_Fault_Number1_31 "故障码1";
CM_ SG_ 2265050799 M2P_AL_Fault_Number2_31 "故障码2";
CM_ SG_ 2265050799 M2P_AL_Fault_Number3_31 "故障码3";
CM_ SG_ 2265050799 M2P_AL_Fault_Number4_31 "故障码4";
CM_ SG_ 2265050799 M2P_AL_Fault_Number5_31 "故障码5";
CM_ SG_ 2265050799 M2P_AL_Fault_Number6_31 "故障码6";
CM_ SG_ 2332159633 M2P_Measure_Vol_01 "MBMU汇总所有高压在线电柜外侧电压平均值                                           ";
CM_ SG_ 2332159633 M2P_Current_01 "所有电柜电流累加和";
CM_ SG_ 2332159633 M2P_SOH_01 "SOH";
CM_ SG_ 2332159633 M2P_RSOC_01 "真实SOC";
CM_ SG_ 2332159633 M2P_DSOC_01 "显示SOC";
CM_ SG_ 2332159633 CMD_of_Closed_Loop_01 "闭环算法开启指令";
CM_ SG_ 2332159633 SOCDiffHighFlg "柜间SOC差异大告警";
CM_ SG_ 2332159634 M2P_Measure_Vol_02 "MBMU汇总所有高压在线电柜外侧电压平均值                                           ";
CM_ SG_ 2332159634 M2P_Current_02 "所有电柜电流累加和";
CM_ SG_ 2332159634 M2P_SOH_02 "SOH";
CM_ SG_ 2332159634 M2P_RSOC_02 "真实SOC";
CM_ SG_ 2332159634 M2P_DSOC_02 "显示SOC";
CM_ SG_ 2332159634 CMD_of_Closed_Loop_02 "闭环算法开启指令";
CM_ SG_ 2332159634 SOCDiffHighFlg "柜间SOC差异大告警";
CM_ SG_ 2332159635 M2P_Measure_Vol_03 "MBMU汇总所有高压在线电柜外侧电压平均值                                           ";
CM_ SG_ 2332159635 M2P_Current_03 "所有电柜电流累加和";
CM_ SG_ 2332159635 M2P_SOH_03 "SOH";
CM_ SG_ 2332159635 M2P_RSOC_03 "真实SOC";
CM_ SG_ 2332159635 M2P_DSOC_03 "显示SOC";
CM_ SG_ 2332159635 CMD_of_Closed_Loop_03 "闭环算法开启指令";
CM_ SG_ 2332159635 SOCDiffHighFlg "柜间SOC差异大告警";
CM_ SG_ 2332159636 M2P_Measure_Vol_04 "MBMU汇总所有高压在线电柜外侧电压平均值                                           ";
CM_ SG_ 2332159636 M2P_Current_04 "所有电柜电流累加和";
CM_ SG_ 2332159636 M2P_SOH_04 "SOH";
CM_ SG_ 2332159636 M2P_RSOC_04 "真实SOC";
CM_ SG_ 2332159636 M2P_DSOC_04 "显示SOC";
CM_ SG_ 2332159636 CMD_of_Closed_Loop_04 "闭环算法开启指令";
CM_ SG_ 2332159636 SOCDiffHighFlg "柜间SOC差异大告警";
CM_ SG_ 2332159637 M2P_Measure_Vol_05 "MBMU汇总所有高压在线电柜外侧电压平均值                                           ";
CM_ SG_ 2332159637 M2P_Current_05 "所有电柜电流累加和";
CM_ SG_ 2332159637 M2P_SOH_05 "SOH";
CM_ SG_ 2332159637 M2P_RSOC_05 "真实SOC";
CM_ SG_ 2332159637 M2P_DSOC_05 "显示SOC";
CM_ SG_ 2332159637 CMD_of_Closed_Loop_05 "闭环算法开启指令";
CM_ SG_ 2332159637 SOCDiffHighFlg "柜间SOC差异大告警";
CM_ SG_ 2332159638 M2P_Measure_Vol_06 "MBMU汇总所有高压在线电柜外侧电压平均值                                           ";
CM_ SG_ 2332159638 M2P_Current_06 "所有电柜电流累加和";
CM_ SG_ 2332159638 M2P_SOH_06 "SOH";
CM_ SG_ 2332159638 M2P_RSOC_06 "真实SOC";
CM_ SG_ 2332159638 M2P_DSOC_06 "显示SOC";
CM_ SG_ 2332159638 CMD_of_Closed_Loop_06 "闭环算法开启指令";
CM_ SG_ 2332159638 SOCDiffHighFlg "柜间SOC差异大告警";
CM_ SG_ 2332159639 M2P_Measure_Vol_07 "MBMU汇总所有高压在线电柜外侧电压平均值                                           ";
CM_ SG_ 2332159639 M2P_Current_07 "所有电柜电流累加和";
CM_ SG_ 2332159639 M2P_SOH_07 "SOH";
CM_ SG_ 2332159639 M2P_RSOC_07 "真实SOC";
CM_ SG_ 2332159639 M2P_DSOC_07 "显示SOC";
CM_ SG_ 2332159639 CMD_of_Closed_Loop_07 "闭环算法开启指令";
CM_ SG_ 2332159639 SOCDiffHighFlg "柜间SOC差异大告警";
CM_ SG_ 2332159640 M2P_Measure_Vol_08 "MBMU汇总所有高压在线电柜外侧电压平均值                                           ";
CM_ SG_ 2332159640 M2P_Current_08 "所有电柜电流累加和";
CM_ SG_ 2332159640 M2P_SOH_08 "SOH";
CM_ SG_ 2332159640 M2P_RSOC_08 "真实SOC";
CM_ SG_ 2332159640 M2P_DSOC_08 "显示SOC";
CM_ SG_ 2332159640 CMD_of_Closed_Loop_08 "闭环算法开启指令";
CM_ SG_ 2332159640 SOCDiffHighFlg "柜间SOC差异大告警";
CM_ SG_ 2332159641 M2P_Measure_Vol_09 "MBMU汇总所有高压在线电柜外侧电压平均值                                           ";
CM_ SG_ 2332159641 M2P_Current_09 "所有电柜电流累加和";
CM_ SG_ 2332159641 M2P_SOH_09 "SOH";
CM_ SG_ 2332159641 M2P_RSOC_09 "真实SOC";
CM_ SG_ 2332159641 M2P_DSOC_09 "显示SOC";
CM_ SG_ 2332159641 CMD_of_Closed_Loop_09 "闭环算法开启指令";
CM_ SG_ 2332159641 SOCDiffHighFlg "柜间SOC差异大告警";
CM_ SG_ 2332159642 M2P_Measure_Vol_10 "MBMU汇总所有高压在线电柜外侧电压平均值                                           ";
CM_ SG_ 2332159642 M2P_Current_10 "所有电柜电流累加和";
CM_ SG_ 2332159642 M2P_SOH_10 "SOH";
CM_ SG_ 2332159642 M2P_RSOC_10 "真实SOC";
CM_ SG_ 2332159642 M2P_DSOC_10 "显示SOC";
CM_ SG_ 2332159642 CMD_of_Closed_Loop_10 "闭环算法开启指令";
CM_ SG_ 2332159642 SOCDiffHighFlg "柜间SOC差异大告警";
CM_ SG_ 2332159643 M2P_Measure_Vol_11 "MBMU汇总所有高压在线电柜外侧电压平均值                                           ";
CM_ SG_ 2332159643 M2P_Current_11 "所有电柜电流累加和";
CM_ SG_ 2332159643 M2P_SOH_11 "SOH";
CM_ SG_ 2332159643 M2P_RSOC_11 "真实SOC";
CM_ SG_ 2332159643 M2P_DSOC_11 "显示SOC";
CM_ SG_ 2332159643 CMD_of_Closed_Loop_11 "闭环算法开启指令";
CM_ SG_ 2332159643 SOCDiffHighFlg "柜间SOC差异大告警";
CM_ SG_ 2332159644 M2P_Measure_Vol_12 "MBMU汇总所有高压在线电柜外侧电压平均值                                           ";
CM_ SG_ 2332159644 M2P_Current_12 "所有电柜电流累加和";
CM_ SG_ 2332159644 M2P_SOH_12 "SOH";
CM_ SG_ 2332159644 M2P_RSOC_12 "真实SOC";
CM_ SG_ 2332159644 M2P_DSOC_12 "显示SOC";
CM_ SG_ 2332159644 CMD_of_Closed_Loop_12 "闭环算法开启指令";
CM_ SG_ 2332159644 SOCDiffHighFlg "柜间SOC差异大告警";
CM_ SG_ 2332159645 M2P_Measure_Vol_13 "MBMU汇总所有高压在线电柜外侧电压平均值                                           ";
CM_ SG_ 2332159645 M2P_Current_13 "所有电柜电流累加和";
CM_ SG_ 2332159645 M2P_SOH_13 "SOH";
CM_ SG_ 2332159645 M2P_RSOC_13 "真实SOC";
CM_ SG_ 2332159645 M2P_DSOC_13 "显示SOC";
CM_ SG_ 2332159645 CMD_of_Closed_Loop_13 "闭环算法开启指令";
CM_ SG_ 2332159645 SOCDiffHighFlg "柜间SOC差异大告警";
CM_ SG_ 2332159646 M2P_Measure_Vol_14 "MBMU汇总所有高压在线电柜外侧电压平均值                                           ";
CM_ SG_ 2332159646 M2P_Current_14 "所有电柜电流累加和";
CM_ SG_ 2332159646 M2P_SOH_14 "SOH";
CM_ SG_ 2332159646 M2P_RSOC_14 "真实SOC";
CM_ SG_ 2332159646 M2P_DSOC_14 "显示SOC";
CM_ SG_ 2332159646 CMD_of_Closed_Loop_14 "闭环算法开启指令";
CM_ SG_ 2332159646 SOCDiffHighFlg "柜间SOC差异大告警";
CM_ SG_ 2332159647 M2P_Measure_Vol_15 "MBMU汇总所有高压在线电柜外侧电压平均值                                           ";
CM_ SG_ 2332159647 M2P_Current_15 "所有电柜电流累加和";
CM_ SG_ 2332159647 M2P_SOH_15 "SOH";
CM_ SG_ 2332159647 M2P_RSOC_15 "真实SOC";
CM_ SG_ 2332159647 M2P_DSOC_15 "显示SOC";
CM_ SG_ 2332159647 CMD_of_Closed_Loop_15 "闭环算法开启指令";
CM_ SG_ 2332159647 SOCDiffHighFlg "柜间SOC差异大告警";
CM_ SG_ 2332159648 M2P_Measure_Vol_16 "MBMU汇总所有高压在线电柜外侧电压平均值                                           ";
CM_ SG_ 2332159648 M2P_Current_16 "所有电柜电流累加和";
CM_ SG_ 2332159648 M2P_SOH_16 "SOH";
CM_ SG_ 2332159648 M2P_RSOC_16 "真实SOC";
CM_ SG_ 2332159648 M2P_DSOC_16 "显示SOC";
CM_ SG_ 2332159648 CMD_of_Closed_Loop_16 "闭环算法开启指令";
CM_ SG_ 2332159648 SOCDiffHighFlg "柜间SOC差异大告警";
CM_ SG_ 2332159649 M2P_Measure_Vol_17 "MBMU汇总所有高压在线电柜外侧电压平均值                                           ";
CM_ SG_ 2332159649 M2P_Current_17 "所有电柜电流累加和";
CM_ SG_ 2332159649 M2P_SOH_17 "SOH";
CM_ SG_ 2332159649 M2P_RSOC_17 "真实SOC";
CM_ SG_ 2332159649 M2P_DSOC_17 "显示SOC";
CM_ SG_ 2332159649 CMD_of_Closed_Loop_17 "闭环算法开启指令";
CM_ SG_ 2332159649 SOCDiffHighFlg "柜间SOC差异大告警";
CM_ SG_ 2332159650 M2P_Measure_Vol_18 "MBMU汇总所有高压在线电柜外侧电压平均值                                           ";
CM_ SG_ 2332159650 M2P_Current_18 "所有电柜电流累加和";
CM_ SG_ 2332159650 M2P_SOH_18 "SOH";
CM_ SG_ 2332159650 M2P_RSOC_18 "真实SOC";
CM_ SG_ 2332159650 M2P_DSOC_18 "显示SOC";
CM_ SG_ 2332159650 CMD_of_Closed_Loop_18 "闭环算法开启指令";
CM_ SG_ 2332159650 SOCDiffHighFlg "柜间SOC差异大告警";
CM_ SG_ 2332159651 M2P_Measure_Vol_19 "MBMU汇总所有高压在线电柜外侧电压平均值                                           ";
CM_ SG_ 2332159651 M2P_Current_19 "所有电柜电流累加和";
CM_ SG_ 2332159651 M2P_SOH_19 "SOH";
CM_ SG_ 2332159651 M2P_RSOC_19 "真实SOC";
CM_ SG_ 2332159651 M2P_DSOC_19 "显示SOC";
CM_ SG_ 2332159651 CMD_of_Closed_Loop_19 "闭环算法开启指令";
CM_ SG_ 2332159651 SOCDiffHighFlg "柜间SOC差异大告警";
CM_ SG_ 2332159652 M2P_Measure_Vol_20 "MBMU汇总所有高压在线电柜外侧电压平均值                                           ";
CM_ SG_ 2332159652 M2P_Current_20 "所有电柜电流累加和";
CM_ SG_ 2332159652 M2P_SOH_20 "SOH";
CM_ SG_ 2332159652 M2P_RSOC_20 "真实SOC";
CM_ SG_ 2332159652 M2P_DSOC_20 "显示SOC";
CM_ SG_ 2332159652 CMD_of_Closed_Loop_20 "闭环算法开启指令";
CM_ SG_ 2332159652 SOCDiffHighFlg "柜间SOC差异大告警";
CM_ SG_ 2332159653 M2P_Measure_Vol_21 "MBMU汇总所有高压在线电柜外侧电压平均值                                           ";
CM_ SG_ 2332159653 M2P_Current_21 "所有电柜电流累加和";
CM_ SG_ 2332159653 M2P_SOH_21 "SOH";
CM_ SG_ 2332159653 M2P_RSOC_21 "真实SOC";
CM_ SG_ 2332159653 M2P_DSOC_21 "显示SOC";
CM_ SG_ 2332159653 CMD_of_Closed_Loop_21 "闭环算法开启指令";
CM_ SG_ 2332159653 SOCDiffHighFlg "柜间SOC差异大告警";
CM_ SG_ 2332159654 M2P_Measure_Vol_22 "MBMU汇总所有高压在线电柜外侧电压平均值                                           ";
CM_ SG_ 2332159654 M2P_Current_22 "所有电柜电流累加和";
CM_ SG_ 2332159654 M2P_SOH_22 "SOH";
CM_ SG_ 2332159654 M2P_RSOC_22 "真实SOC";
CM_ SG_ 2332159654 M2P_DSOC_22 "显示SOC";
CM_ SG_ 2332159654 CMD_of_Closed_Loop_22 "闭环算法开启指令";
CM_ SG_ 2332159654 SOCDiffHighFlg "柜间SOC差异大告警";
CM_ SG_ 2332159655 M2P_Measure_Vol_23 "MBMU汇总所有高压在线电柜外侧电压平均值                                           ";
CM_ SG_ 2332159655 M2P_Current_23 "所有电柜电流累加和";
CM_ SG_ 2332159655 M2P_SOH_23 "SOH";
CM_ SG_ 2332159655 M2P_RSOC_23 "真实SOC";
CM_ SG_ 2332159655 M2P_DSOC_23 "显示SOC";
CM_ SG_ 2332159655 CMD_of_Closed_Loop_23 "闭环算法开启指令";
CM_ SG_ 2332159655 SOCDiffHighFlg "柜间SOC差异大告警";
CM_ SG_ 2332159656 M2P_Measure_Vol_24 "MBMU汇总所有高压在线电柜外侧电压平均值                                           ";
CM_ SG_ 2332159656 M2P_Current_24 "所有电柜电流累加和";
CM_ SG_ 2332159656 M2P_SOH_24 "SOH";
CM_ SG_ 2332159656 M2P_RSOC_24 "真实SOC";
CM_ SG_ 2332159656 M2P_DSOC_24 "显示SOC";
CM_ SG_ 2332159656 CMD_of_Closed_Loop_24 "闭环算法开启指令";
CM_ SG_ 2332159656 SOCDiffHighFlg "柜间SOC差异大告警";
CM_ SG_ 2332159657 M2P_Measure_Vol_25 "MBMU汇总所有高压在线电柜外侧电压平均值                                           ";
CM_ SG_ 2332159657 M2P_Current_25 "所有电柜电流累加和";
CM_ SG_ 2332159657 M2P_SOH_25 "SOH";
CM_ SG_ 2332159657 M2P_RSOC_25 "真实SOC";
CM_ SG_ 2332159657 M2P_DSOC_25 "显示SOC";
CM_ SG_ 2332159657 CMD_of_Closed_Loop_25 "闭环算法开启指令";
CM_ SG_ 2332159657 SOCDiffHighFlg "柜间SOC差异大告警";
CM_ SG_ 2332159658 M2P_Measure_Vol_26 "MBMU汇总所有高压在线电柜外侧电压平均值                                           ";
CM_ SG_ 2332159658 M2P_Current_26 "所有电柜电流累加和";
CM_ SG_ 2332159658 M2P_SOH_26 "SOH";
CM_ SG_ 2332159658 M2P_RSOC_26 "真实SOC";
CM_ SG_ 2332159658 M2P_DSOC_26 "显示SOC";
CM_ SG_ 2332159658 CMD_of_Closed_Loop_26 "闭环算法开启指令";
CM_ SG_ 2332159658 SOCDiffHighFlg "柜间SOC差异大告警";
CM_ SG_ 2332159659 M2P_Measure_Vol_27 "MBMU汇总所有高压在线电柜外侧电压平均值                                           ";
CM_ SG_ 2332159659 M2P_Current_27 "所有电柜电流累加和";
CM_ SG_ 2332159659 M2P_SOH_27 "SOH";
CM_ SG_ 2332159659 M2P_RSOC_27 "真实SOC";
CM_ SG_ 2332159659 M2P_DSOC_27 "显示SOC";
CM_ SG_ 2332159659 CMD_of_Closed_Loop_27 "闭环算法开启指令";
CM_ SG_ 2332159659 SOCDiffHighFlg "柜间SOC差异大告警";
CM_ SG_ 2332159660 M2P_Measure_Vol_28 "MBMU汇总所有高压在线电柜外侧电压平均值                                           ";
CM_ SG_ 2332159660 M2P_Current_28 "所有电柜电流累加和";
CM_ SG_ 2332159660 M2P_SOH_28 "SOH";
CM_ SG_ 2332159660 M2P_RSOC_28 "真实SOC";
CM_ SG_ 2332159660 M2P_DSOC_28 "显示SOC";
CM_ SG_ 2332159660 CMD_of_Closed_Loop_28 "闭环算法开启指令";
CM_ SG_ 2332159660 SOCDiffHighFlg "柜间SOC差异大告警";
CM_ SG_ 2332159661 M2P_Measure_Vol_29 "MBMU汇总所有高压在线电柜外侧电压平均值                                           ";
CM_ SG_ 2332159661 M2P_Current_29 "所有电柜电流累加和";
CM_ SG_ 2332159661 M2P_SOH_29 "SOH";
CM_ SG_ 2332159661 M2P_RSOC_29 "真实SOC";
CM_ SG_ 2332159661 M2P_DSOC_29 "显示SOC";
CM_ SG_ 2332159661 CMD_of_Closed_Loop_29 "闭环算法开启指令";
CM_ SG_ 2332159661 SOCDiffHighFlg "柜间SOC差异大告警";
CM_ SG_ 2332159662 M2P_Measure_Vol_30 "MBMU汇总所有高压在线电柜外侧电压平均值                                           ";
CM_ SG_ 2332159662 M2P_Current_30 "所有电柜电流累加和";
CM_ SG_ 2332159662 M2P_SOH_30 "SOH";
CM_ SG_ 2332159662 M2P_RSOC_30 "真实SOC";
CM_ SG_ 2332159662 M2P_DSOC_30 "显示SOC";
CM_ SG_ 2332159662 CMD_of_Closed_Loop_30 "闭环算法开启指令";
CM_ SG_ 2332159662 SOCDiffHighFlg "柜间SOC差异大告警";
CM_ SG_ 2332159663 M2P_Measure_Vol_31 "MBMU汇总所有高压在线电柜外侧电压平均值                                           ";
CM_ SG_ 2332159663 M2P_Current_31 "所有电柜电流累加和";
CM_ SG_ 2332159663 M2P_SOH_31 "SOH";
CM_ SG_ 2332159663 M2P_RSOC_31 "真实SOC";
CM_ SG_ 2332159663 M2P_DSOC_31 "显示SOC";
CM_ SG_ 2332159663 CMD_of_Closed_Loop_31 "闭环算法开启指令";
CM_ SG_ 2332159663 SOCDiffHighFlg "柜间SOC差异大告警";
CM_ SG_ 2332225169 M2P_LifeSignal_01 "生命帧信号 0~15";
CM_ SG_ 2332225169 M2P_ST_Power_01 "系统上高压状态                                    ";
CM_ SG_ 2332225169 M2P_ST_Master_slave_01 "主从集装箱架构状态";
CM_ SG_ 2332225169 M2P_Status_Fan_SW_01 "MBMU风扇控制继电器状态  ？MBMU控制电箱的风扇，确认内容//
2022/10/21
发送信号ScSTMS_FanCtrState";
CM_ SG_ 2332225169 M2P_Circuit_Breaker_01 "断路器状态，各个SBMU的高压上电状态";
CM_ SG_ 2332225169 M2P_NUM_OF_SlaveMBMU "系统中MBMU的总数量";
CM_ SG_ 2332225169 M2P_RackInhabitResult "电柜高压隔离结果";
CM_ SG_ 2332225169 M2P_STofSBMUAutoCoding_01 "SBMU地址自动编码状态";
CM_ SG_ 2332225169 M2P_LvSelfLock "MBMU电源自锁使能标志";
CM_ SG_ 2332225169 M2P_SbmuPwrOnFlg "SBMU供电完成标志";
CM_ SG_ 2332225169 M2P_InsulPwrOnFlg "IMM板供电完成标志";
CM_ SG_ 2332225169 M2P_HvOffReqFlg "高压继电器断开请求标志";
CM_ SG_ 2332225169 M2P_HvOnAllowFlg "低压上下电模块允许高压上电标志";
CM_ SG_ 2332225169 M2P_SBMULvoffAbnomal "SBMU异常下电标志";
CM_ SG_ 2332225169 M2P_LVPwrDFaultR "低压下电失败原因 ";
CM_ SG_ 2332225169 M2P_SysRunState "系统运行状态                                    ";
CM_ SG_ 2332225169 M2P_MIN_NUM_OF_ONLINE_SBMU "MBMU发送给 PC和ETH　最小运行给SBMU数量(预留，暂未实现)";
CM_ SG_ 2332225169 MBMU_Tank_Num_RelayOn "MBMU发送给 PCS 的在线电柜数量";
CM_ SG_ 2332225169 M2P_NUM_OF_SBMU "系统配置SBMU数量";
CM_ SG_ 2332225170 M2P_LifeSignal_02 "生命帧信号 0~15";
CM_ SG_ 2332225170 M2P_ST_Power_02 "系统上高压状态                                    ";
CM_ SG_ 2332225170 M2P_ST_Master_slave_02 "主从集装箱架构状态";
CM_ SG_ 2332225170 M2P_Status_Fan_SW_02 "MBMU风扇控制继电器状态  ？MBMU控制电箱的风扇，确认内容//
2022/10/21
发送信号ScSTMS_FanCtrState";
CM_ SG_ 2332225170 M2P_Circuit_Breaker_02 "断路器状态，各个SBMU的高压上电状态";
CM_ SG_ 2332225170 M2P_NUM_OF_SlaveMBMU "系统中MBMU的总数量";
CM_ SG_ 2332225170 M2P_RackInhabitResult "电柜高压隔离结果";
CM_ SG_ 2332225170 M2P_STofSBMUAutoCoding_02 "SBMU地址自动编码状态";
CM_ SG_ 2332225170 M2P_LvSelfLock "MBMU电源自锁使能标志";
CM_ SG_ 2332225170 M2P_SbmuPwrOnFlg "SBMU供电完成标志";
CM_ SG_ 2332225170 M2P_InsulPwrOnFlg "IMM板供电完成标志";
CM_ SG_ 2332225170 M2P_HvOffReqFlg "高压继电器断开请求标志";
CM_ SG_ 2332225170 M2P_HvOnAllowFlg "低压上下电模块允许高压上电标志";
CM_ SG_ 2332225170 M2P_SBMULvoffAbnomal "SBMU异常下电标志";
CM_ SG_ 2332225170 M2P_LVPwrDFaultR "低压下电失败原因 ";
CM_ SG_ 2332225170 M2P_SysRunState "系统运行状态                                    ";
CM_ SG_ 2332225170 M2P_MIN_NUM_OF_ONLINE_SBMU "MBMU发送给 PC和ETH　最小运行给SBMU数量(预留，暂未实现)";
CM_ SG_ 2332225170 MBMU_Tank_Num_RelayOn "MBMU发送给 PCS 的在线电柜数量";
CM_ SG_ 2332225170 M2P_NUM_OF_SBMU "系统配置SBMU数量";
CM_ SG_ 2332225171 M2P_LifeSignal_03 "生命帧信号 0~15";
CM_ SG_ 2332225171 M2P_ST_Power_03 "系统上高压状态                                    ";
CM_ SG_ 2332225171 M2P_ST_Master_slave_03 "主从集装箱架构状态";
CM_ SG_ 2332225171 M2P_Status_Fan_SW_03 "MBMU风扇控制继电器状态  ？MBMU控制电箱的风扇，确认内容//
2022/10/21
发送信号ScSTMS_FanCtrState";
CM_ SG_ 2332225171 M2P_Circuit_Breaker_03 "断路器状态，各个SBMU的高压上电状态";
CM_ SG_ 2332225171 M2P_NUM_OF_SlaveMBMU "系统中MBMU的总数量";
CM_ SG_ 2332225171 M2P_RackInhabitResult "电柜高压隔离结果";
CM_ SG_ 2332225171 M2P_STofSBMUAutoCoding_03 "SBMU地址自动编码状态";
CM_ SG_ 2332225171 M2P_LvSelfLock "MBMU电源自锁使能标志";
CM_ SG_ 2332225171 M2P_SbmuPwrOnFlg "SBMU供电完成标志";
CM_ SG_ 2332225171 M2P_InsulPwrOnFlg "IMM板供电完成标志";
CM_ SG_ 2332225171 M2P_HvOffReqFlg "高压继电器断开请求标志";
CM_ SG_ 2332225171 M2P_HvOnAllowFlg "低压上下电模块允许高压上电标志";
CM_ SG_ 2332225171 M2P_SBMULvoffAbnomal "SBMU异常下电标志";
CM_ SG_ 2332225171 M2P_LVPwrDFaultR "低压下电失败原因 ";
CM_ SG_ 2332225171 M2P_SysRunState "系统运行状态                                    ";
CM_ SG_ 2332225171 M2P_MIN_NUM_OF_ONLINE_SBMU "MBMU发送给 PC和ETH　最小运行给SBMU数量(预留，暂未实现)";
CM_ SG_ 2332225171 MBMU_Tank_Num_RelayOn "MBMU发送给 PCS 的在线电柜数量";
CM_ SG_ 2332225171 M2P_NUM_OF_SBMU "系统配置SBMU数量";
CM_ SG_ 2332225172 M2P_LifeSignal_04 "生命帧信号 0~15";
CM_ SG_ 2332225172 M2P_ST_Power_04 "系统上高压状态                                    ";
CM_ SG_ 2332225172 M2P_ST_Master_slave_04 "主从集装箱架构状态";
CM_ SG_ 2332225172 M2P_Status_Fan_SW_04 "MBMU风扇控制继电器状态  ？MBMU控制电箱的风扇，确认内容//
2022/10/21
发送信号ScSTMS_FanCtrState";
CM_ SG_ 2332225172 M2P_Circuit_Breaker_04 "断路器状态，各个SBMU的高压上电状态";
CM_ SG_ 2332225172 M2P_NUM_OF_SlaveMBMU "系统中MBMU的总数量";
CM_ SG_ 2332225172 M2P_RackInhabitResult "电柜高压隔离结果";
CM_ SG_ 2332225172 M2P_STofSBMUAutoCoding_04 "SBMU地址自动编码状态";
CM_ SG_ 2332225172 M2P_LvSelfLock "MBMU电源自锁使能标志";
CM_ SG_ 2332225172 M2P_SbmuPwrOnFlg "SBMU供电完成标志";
CM_ SG_ 2332225172 M2P_InsulPwrOnFlg "IMM板供电完成标志";
CM_ SG_ 2332225172 M2P_HvOffReqFlg "高压继电器断开请求标志";
CM_ SG_ 2332225172 M2P_HvOnAllowFlg "低压上下电模块允许高压上电标志";
CM_ SG_ 2332225172 M2P_SBMULvoffAbnomal "SBMU异常下电标志";
CM_ SG_ 2332225172 M2P_LVPwrDFaultR "低压下电失败原因 ";
CM_ SG_ 2332225172 M2P_SysRunState "系统运行状态                                    ";
CM_ SG_ 2332225172 M2P_MIN_NUM_OF_ONLINE_SBMU "MBMU发送给 PC和ETH　最小运行给SBMU数量(预留，暂未实现)";
CM_ SG_ 2332225172 MBMU_Tank_Num_RelayOn "MBMU发送给 PCS 的在线电柜数量";
CM_ SG_ 2332225172 M2P_NUM_OF_SBMU "系统配置SBMU数量";
CM_ SG_ 2332225173 M2P_LifeSignal_05 "生命帧信号 0~15";
CM_ SG_ 2332225173 M2P_ST_Power_05 "系统上高压状态                                    ";
CM_ SG_ 2332225173 M2P_ST_Master_slave_05 "主从集装箱架构状态";
CM_ SG_ 2332225173 M2P_Status_Fan_SW_05 "MBMU风扇控制继电器状态  ？MBMU控制电箱的风扇，确认内容//
2022/10/21
发送信号ScSTMS_FanCtrState";
CM_ SG_ 2332225173 M2P_Circuit_Breaker_05 "断路器状态，各个SBMU的高压上电状态";
CM_ SG_ 2332225173 M2P_NUM_OF_SlaveMBMU "系统中MBMU的总数量";
CM_ SG_ 2332225173 M2P_RackInhabitResult "电柜高压隔离结果";
CM_ SG_ 2332225173 M2P_STofSBMUAutoCoding_05 "SBMU地址自动编码状态";
CM_ SG_ 2332225173 M2P_LvSelfLock "MBMU电源自锁使能标志";
CM_ SG_ 2332225173 M2P_SbmuPwrOnFlg "SBMU供电完成标志";
CM_ SG_ 2332225173 M2P_InsulPwrOnFlg "IMM板供电完成标志";
CM_ SG_ 2332225173 M2P_HvOffReqFlg "高压继电器断开请求标志";
CM_ SG_ 2332225173 M2P_HvOnAllowFlg "低压上下电模块允许高压上电标志";
CM_ SG_ 2332225173 M2P_SBMULvoffAbnomal "SBMU异常下电标志";
CM_ SG_ 2332225173 M2P_LVPwrDFaultR "低压下电失败原因 ";
CM_ SG_ 2332225173 M2P_SysRunState "系统运行状态                                    ";
CM_ SG_ 2332225173 M2P_MIN_NUM_OF_ONLINE_SBMU "MBMU发送给 PC和ETH　最小运行给SBMU数量(预留，暂未实现)";
CM_ SG_ 2332225173 MBMU_Tank_Num_RelayOn "MBMU发送给 PCS 的在线电柜数量";
CM_ SG_ 2332225173 M2P_NUM_OF_SBMU "系统配置SBMU数量";
CM_ SG_ 2332225174 M2P_LifeSignal_06 "生命帧信号 0~15";
CM_ SG_ 2332225174 M2P_ST_Power_06 "系统上高压状态                                    ";
CM_ SG_ 2332225174 M2P_ST_Master_slave_06 "主从集装箱架构状态";
CM_ SG_ 2332225174 M2P_Status_Fan_SW_06 "MBMU风扇控制继电器状态  ？MBMU控制电箱的风扇，确认内容//
2022/10/21
发送信号ScSTMS_FanCtrState";
CM_ SG_ 2332225174 M2P_Circuit_Breaker_06 "断路器状态，各个SBMU的高压上电状态";
CM_ SG_ 2332225174 M2P_NUM_OF_SlaveMBMU "系统中MBMU的总数量";
CM_ SG_ 2332225174 M2P_RackInhabitResult "电柜高压隔离结果";
CM_ SG_ 2332225174 M2P_STofSBMUAutoCoding_06 "SBMU地址自动编码状态";
CM_ SG_ 2332225174 M2P_LvSelfLock "MBMU电源自锁使能标志";
CM_ SG_ 2332225174 M2P_SbmuPwrOnFlg "SBMU供电完成标志";
CM_ SG_ 2332225174 M2P_InsulPwrOnFlg "IMM板供电完成标志";
CM_ SG_ 2332225174 M2P_HvOffReqFlg "高压继电器断开请求标志";
CM_ SG_ 2332225174 M2P_HvOnAllowFlg "低压上下电模块允许高压上电标志";
CM_ SG_ 2332225174 M2P_SBMULvoffAbnomal "SBMU异常下电标志";
CM_ SG_ 2332225174 M2P_LVPwrDFaultR "低压下电失败原因 ";
CM_ SG_ 2332225174 M2P_SysRunState "系统运行状态                                    ";
CM_ SG_ 2332225174 M2P_MIN_NUM_OF_ONLINE_SBMU "MBMU发送给 PC和ETH　最小运行给SBMU数量(预留，暂未实现)";
CM_ SG_ 2332225174 MBMU_Tank_Num_RelayOn "MBMU发送给 PCS 的在线电柜数量";
CM_ SG_ 2332225174 M2P_NUM_OF_SBMU "系统配置SBMU数量";
CM_ SG_ 2332225175 M2P_LifeSignal_07 "生命帧信号 0~15";
CM_ SG_ 2332225175 M2P_ST_Power_07 "系统上高压状态                                    ";
CM_ SG_ 2332225175 M2P_ST_Master_slave_07 "主从集装箱架构状态";
CM_ SG_ 2332225175 M2P_Status_Fan_SW_07 "MBMU风扇控制继电器状态  ？MBMU控制电箱的风扇，确认内容//
2022/10/21
发送信号ScSTMS_FanCtrState";
CM_ SG_ 2332225175 M2P_Circuit_Breaker_07 "断路器状态，各个SBMU的高压上电状态";
CM_ SG_ 2332225175 M2P_NUM_OF_SlaveMBMU "系统中MBMU的总数量";
CM_ SG_ 2332225175 M2P_RackInhabitResult "电柜高压隔离结果";
CM_ SG_ 2332225175 M2P_STofSBMUAutoCoding_07 "SBMU地址自动编码状态";
CM_ SG_ 2332225175 M2P_LvSelfLock "MBMU电源自锁使能标志";
CM_ SG_ 2332225175 M2P_SbmuPwrOnFlg "SBMU供电完成标志";
CM_ SG_ 2332225175 M2P_InsulPwrOnFlg "IMM板供电完成标志";
CM_ SG_ 2332225175 M2P_HvOffReqFlg "高压继电器断开请求标志";
CM_ SG_ 2332225175 M2P_HvOnAllowFlg "低压上下电模块允许高压上电标志";
CM_ SG_ 2332225175 M2P_SBMULvoffAbnomal "SBMU异常下电标志";
CM_ SG_ 2332225175 M2P_LVPwrDFaultR "低压下电失败原因 ";
CM_ SG_ 2332225175 M2P_SysRunState "系统运行状态                                    ";
CM_ SG_ 2332225175 M2P_MIN_NUM_OF_ONLINE_SBMU "MBMU发送给 PC和ETH　最小运行给SBMU数量(预留，暂未实现)";
CM_ SG_ 2332225175 MBMU_Tank_Num_RelayOn "MBMU发送给 PCS 的在线电柜数量";
CM_ SG_ 2332225175 M2P_NUM_OF_SBMU "系统配置SBMU数量";
CM_ SG_ 2332225176 M2P_LifeSignal_08 "生命帧信号 0~15";
CM_ SG_ 2332225176 M2P_ST_Power_08 "系统上高压状态                                    ";
CM_ SG_ 2332225176 M2P_ST_Master_slave_08 "主从集装箱架构状态";
CM_ SG_ 2332225176 M2P_Status_Fan_SW_08 "MBMU风扇控制继电器状态  ？MBMU控制电箱的风扇，确认内容//
2022/10/21
发送信号ScSTMS_FanCtrState";
CM_ SG_ 2332225176 M2P_Circuit_Breaker_08 "断路器状态，各个SBMU的高压上电状态";
CM_ SG_ 2332225176 M2P_NUM_OF_SlaveMBMU "系统中MBMU的总数量";
CM_ SG_ 2332225176 M2P_RackInhabitResult "电柜高压隔离结果";
CM_ SG_ 2332225176 M2P_STofSBMUAutoCoding_08 "SBMU地址自动编码状态";
CM_ SG_ 2332225176 M2P_LvSelfLock "MBMU电源自锁使能标志";
CM_ SG_ 2332225176 M2P_SbmuPwrOnFlg "SBMU供电完成标志";
CM_ SG_ 2332225176 M2P_InsulPwrOnFlg "IMM板供电完成标志";
CM_ SG_ 2332225176 M2P_HvOffReqFlg "高压继电器断开请求标志";
CM_ SG_ 2332225176 M2P_HvOnAllowFlg "低压上下电模块允许高压上电标志";
CM_ SG_ 2332225176 M2P_SBMULvoffAbnomal "SBMU异常下电标志";
CM_ SG_ 2332225176 M2P_LVPwrDFaultR "低压下电失败原因 ";
CM_ SG_ 2332225176 M2P_SysRunState "系统运行状态                                    ";
CM_ SG_ 2332225176 M2P_MIN_NUM_OF_ONLINE_SBMU "MBMU发送给 PC和ETH　最小运行给SBMU数量(预留，暂未实现)";
CM_ SG_ 2332225176 MBMU_Tank_Num_RelayOn "MBMU发送给 PCS 的在线电柜数量";
CM_ SG_ 2332225176 M2P_NUM_OF_SBMU "系统配置SBMU数量";
CM_ SG_ 2332225177 M2P_LifeSignal_09 "生命帧信号 0~15";
CM_ SG_ 2332225177 M2P_ST_Power_09 "系统上高压状态                                    ";
CM_ SG_ 2332225177 M2P_ST_Master_slave_09 "主从集装箱架构状态";
CM_ SG_ 2332225177 M2P_Status_Fan_SW_09 "MBMU风扇控制继电器状态  ？MBMU控制电箱的风扇，确认内容//
2022/10/21
发送信号ScSTMS_FanCtrState";
CM_ SG_ 2332225177 M2P_Circuit_Breaker_09 "断路器状态，各个SBMU的高压上电状态";
CM_ SG_ 2332225177 M2P_NUM_OF_SlaveMBMU "系统中MBMU的总数量";
CM_ SG_ 2332225177 M2P_RackInhabitResult "电柜高压隔离结果";
CM_ SG_ 2332225177 M2P_STofSBMUAutoCoding_09 "SBMU地址自动编码状态";
CM_ SG_ 2332225177 M2P_LvSelfLock "MBMU电源自锁使能标志";
CM_ SG_ 2332225177 M2P_SbmuPwrOnFlg "SBMU供电完成标志";
CM_ SG_ 2332225177 M2P_InsulPwrOnFlg "IMM板供电完成标志";
CM_ SG_ 2332225177 M2P_HvOffReqFlg "高压继电器断开请求标志";
CM_ SG_ 2332225177 M2P_HvOnAllowFlg "低压上下电模块允许高压上电标志";
CM_ SG_ 2332225177 M2P_SBMULvoffAbnomal "SBMU异常下电标志";
CM_ SG_ 2332225177 M2P_LVPwrDFaultR "低压下电失败原因 ";
CM_ SG_ 2332225177 M2P_SysRunState "系统运行状态                                    ";
CM_ SG_ 2332225177 M2P_MIN_NUM_OF_ONLINE_SBMU "MBMU发送给 PC和ETH　最小运行给SBMU数量(预留，暂未实现)";
CM_ SG_ 2332225177 MBMU_Tank_Num_RelayOn "MBMU发送给 PCS 的在线电柜数量";
CM_ SG_ 2332225177 M2P_NUM_OF_SBMU "系统配置SBMU数量";
CM_ SG_ 2332225178 M2P_LifeSignal_10 "生命帧信号 0~15";
CM_ SG_ 2332225178 M2P_ST_Power_10 "系统上高压状态                                    ";
CM_ SG_ 2332225178 M2P_ST_Master_slave_10 "主从集装箱架构状态";
CM_ SG_ 2332225178 M2P_Status_Fan_SW_10 "MBMU风扇控制继电器状态  ？MBMU控制电箱的风扇，确认内容//
2022/10/21
发送信号ScSTMS_FanCtrState";
CM_ SG_ 2332225178 M2P_Circuit_Breaker_10 "断路器状态，各个SBMU的高压上电状态";
CM_ SG_ 2332225178 M2P_NUM_OF_SlaveMBMU "系统中MBMU的总数量";
CM_ SG_ 2332225178 M2P_RackInhabitResult "电柜高压隔离结果";
CM_ SG_ 2332225178 M2P_STofSBMUAutoCoding_10 "SBMU地址自动编码状态";
CM_ SG_ 2332225178 M2P_LvSelfLock "MBMU电源自锁使能标志";
CM_ SG_ 2332225178 M2P_SbmuPwrOnFlg "SBMU供电完成标志";
CM_ SG_ 2332225178 M2P_InsulPwrOnFlg "IMM板供电完成标志";
CM_ SG_ 2332225178 M2P_HvOffReqFlg "高压继电器断开请求标志";
CM_ SG_ 2332225178 M2P_HvOnAllowFlg "低压上下电模块允许高压上电标志";
CM_ SG_ 2332225178 M2P_SBMULvoffAbnomal "SBMU异常下电标志";
CM_ SG_ 2332225178 M2P_LVPwrDFaultR "低压下电失败原因 ";
CM_ SG_ 2332225178 M2P_SysRunState "系统运行状态                                    ";
CM_ SG_ 2332225178 M2P_MIN_NUM_OF_ONLINE_SBMU "MBMU发送给 PC和ETH　最小运行给SBMU数量(预留，暂未实现)";
CM_ SG_ 2332225178 MBMU_Tank_Num_RelayOn "MBMU发送给 PCS 的在线电柜数量";
CM_ SG_ 2332225178 M2P_NUM_OF_SBMU "系统配置SBMU数量";
CM_ SG_ 2332225179 M2P_LifeSignal_11 "生命帧信号 0~15";
CM_ SG_ 2332225179 M2P_ST_Power_11 "系统上高压状态                                    ";
CM_ SG_ 2332225179 M2P_ST_Master_slave_11 "主从集装箱架构状态";
CM_ SG_ 2332225179 M2P_Status_Fan_SW_11 "MBMU风扇控制继电器状态  ？MBMU控制电箱的风扇，确认内容//
2022/10/21
发送信号ScSTMS_FanCtrState";
CM_ SG_ 2332225179 M2P_Circuit_Breaker_11 "断路器状态，各个SBMU的高压上电状态";
CM_ SG_ 2332225179 M2P_NUM_OF_SlaveMBMU "系统中MBMU的总数量";
CM_ SG_ 2332225179 M2P_RackInhabitResult "电柜高压隔离结果";
CM_ SG_ 2332225179 M2P_STofSBMUAutoCoding_11 "SBMU地址自动编码状态";
CM_ SG_ 2332225179 M2P_LvSelfLock "MBMU电源自锁使能标志";
CM_ SG_ 2332225179 M2P_SbmuPwrOnFlg "SBMU供电完成标志";
CM_ SG_ 2332225179 M2P_InsulPwrOnFlg "IMM板供电完成标志";
CM_ SG_ 2332225179 M2P_HvOffReqFlg "高压继电器断开请求标志";
CM_ SG_ 2332225179 M2P_HvOnAllowFlg "低压上下电模块允许高压上电标志";
CM_ SG_ 2332225179 M2P_SBMULvoffAbnomal "SBMU异常下电标志";
CM_ SG_ 2332225179 M2P_LVPwrDFaultR "低压下电失败原因 ";
CM_ SG_ 2332225179 M2P_SysRunState "系统运行状态                                    ";
CM_ SG_ 2332225179 M2P_MIN_NUM_OF_ONLINE_SBMU "MBMU发送给 PC和ETH　最小运行给SBMU数量(预留，暂未实现)";
CM_ SG_ 2332225179 MBMU_Tank_Num_RelayOn "MBMU发送给 PCS 的在线电柜数量";
CM_ SG_ 2332225179 M2P_NUM_OF_SBMU "系统配置SBMU数量";
CM_ SG_ 2332225180 M2P_LifeSignal_12 "生命帧信号 0~15";
CM_ SG_ 2332225180 M2P_ST_Power_12 "系统上高压状态                                    ";
CM_ SG_ 2332225180 M2P_ST_Master_slave_12 "主从集装箱架构状态";
CM_ SG_ 2332225180 M2P_Status_Fan_SW_12 "MBMU风扇控制继电器状态  ？MBMU控制电箱的风扇，确认内容//
2022/10/21
发送信号ScSTMS_FanCtrState";
CM_ SG_ 2332225180 M2P_Circuit_Breaker_12 "断路器状态，各个SBMU的高压上电状态";
CM_ SG_ 2332225180 M2P_NUM_OF_SlaveMBMU "系统中MBMU的总数量";
CM_ SG_ 2332225180 M2P_RackInhabitResult "电柜高压隔离结果";
CM_ SG_ 2332225180 M2P_STofSBMUAutoCoding_12 "SBMU地址自动编码状态";
CM_ SG_ 2332225180 M2P_LvSelfLock "MBMU电源自锁使能标志";
CM_ SG_ 2332225180 M2P_SbmuPwrOnFlg "SBMU供电完成标志";
CM_ SG_ 2332225180 M2P_InsulPwrOnFlg "IMM板供电完成标志";
CM_ SG_ 2332225180 M2P_HvOffReqFlg "高压继电器断开请求标志";
CM_ SG_ 2332225180 M2P_HvOnAllowFlg "低压上下电模块允许高压上电标志";
CM_ SG_ 2332225180 M2P_SBMULvoffAbnomal "SBMU异常下电标志";
CM_ SG_ 2332225180 M2P_LVPwrDFaultR "低压下电失败原因 ";
CM_ SG_ 2332225180 M2P_SysRunState "系统运行状态                                    ";
CM_ SG_ 2332225180 M2P_MIN_NUM_OF_ONLINE_SBMU "MBMU发送给 PC和ETH　最小运行给SBMU数量(预留，暂未实现)";
CM_ SG_ 2332225180 MBMU_Tank_Num_RelayOn "MBMU发送给 PCS 的在线电柜数量";
CM_ SG_ 2332225180 M2P_NUM_OF_SBMU "系统配置SBMU数量";
CM_ SG_ 2332225181 M2P_LifeSignal_13 "生命帧信号 0~15";
CM_ SG_ 2332225181 M2P_ST_Power_13 "系统上高压状态                                    ";
CM_ SG_ 2332225181 M2P_ST_Master_slave_13 "主从集装箱架构状态";
CM_ SG_ 2332225181 M2P_Status_Fan_SW_13 "MBMU风扇控制继电器状态  ？MBMU控制电箱的风扇，确认内容//
2022/10/21
发送信号ScSTMS_FanCtrState";
CM_ SG_ 2332225181 M2P_Circuit_Breaker_13 "断路器状态，各个SBMU的高压上电状态";
CM_ SG_ 2332225181 M2P_NUM_OF_SlaveMBMU "系统中MBMU的总数量";
CM_ SG_ 2332225181 M2P_RackInhabitResult "电柜高压隔离结果";
CM_ SG_ 2332225181 M2P_STofSBMUAutoCoding_13 "SBMU地址自动编码状态";
CM_ SG_ 2332225181 M2P_LvSelfLock "MBMU电源自锁使能标志";
CM_ SG_ 2332225181 M2P_SbmuPwrOnFlg "SBMU供电完成标志";
CM_ SG_ 2332225181 M2P_InsulPwrOnFlg "IMM板供电完成标志";
CM_ SG_ 2332225181 M2P_HvOffReqFlg "高压继电器断开请求标志";
CM_ SG_ 2332225181 M2P_HvOnAllowFlg "低压上下电模块允许高压上电标志";
CM_ SG_ 2332225181 M2P_SBMULvoffAbnomal "SBMU异常下电标志";
CM_ SG_ 2332225181 M2P_LVPwrDFaultR "低压下电失败原因 ";
CM_ SG_ 2332225181 M2P_SysRunState "系统运行状态                                    ";
CM_ SG_ 2332225181 M2P_MIN_NUM_OF_ONLINE_SBMU "MBMU发送给 PC和ETH　最小运行给SBMU数量(预留，暂未实现)";
CM_ SG_ 2332225181 MBMU_Tank_Num_RelayOn "MBMU发送给 PCS 的在线电柜数量";
CM_ SG_ 2332225181 M2P_NUM_OF_SBMU "系统配置SBMU数量";
CM_ SG_ 2332225182 M2P_LifeSignal_14 "生命帧信号 0~15";
CM_ SG_ 2332225182 M2P_ST_Power_14 "系统上高压状态                                    ";
CM_ SG_ 2332225182 M2P_ST_Master_slave_14 "主从集装箱架构状态";
CM_ SG_ 2332225182 M2P_Status_Fan_SW_14 "MBMU风扇控制继电器状态  ？MBMU控制电箱的风扇，确认内容//
2022/10/21
发送信号ScSTMS_FanCtrState";
CM_ SG_ 2332225182 M2P_Circuit_Breaker_14 "断路器状态，各个SBMU的高压上电状态";
CM_ SG_ 2332225182 M2P_NUM_OF_SlaveMBMU "系统中MBMU的总数量";
CM_ SG_ 2332225182 M2P_RackInhabitResult "电柜高压隔离结果";
CM_ SG_ 2332225182 M2P_STofSBMUAutoCoding_14 "SBMU地址自动编码状态";
CM_ SG_ 2332225182 M2P_LvSelfLock "MBMU电源自锁使能标志";
CM_ SG_ 2332225182 M2P_SbmuPwrOnFlg "SBMU供电完成标志";
CM_ SG_ 2332225182 M2P_InsulPwrOnFlg "IMM板供电完成标志";
CM_ SG_ 2332225182 M2P_HvOffReqFlg "高压继电器断开请求标志";
CM_ SG_ 2332225182 M2P_HvOnAllowFlg "低压上下电模块允许高压上电标志";
CM_ SG_ 2332225182 M2P_SBMULvoffAbnomal "SBMU异常下电标志";
CM_ SG_ 2332225182 M2P_LVPwrDFaultR "低压下电失败原因 ";
CM_ SG_ 2332225182 M2P_SysRunState "系统运行状态                                    ";
CM_ SG_ 2332225182 M2P_MIN_NUM_OF_ONLINE_SBMU "MBMU发送给 PC和ETH　最小运行给SBMU数量(预留，暂未实现)";
CM_ SG_ 2332225182 MBMU_Tank_Num_RelayOn "MBMU发送给 PCS 的在线电柜数量";
CM_ SG_ 2332225182 M2P_NUM_OF_SBMU "系统配置SBMU数量";
CM_ SG_ 2332225183 M2P_LifeSignal_15 "生命帧信号 0~15";
CM_ SG_ 2332225183 M2P_ST_Power_15 "系统上高压状态                                    ";
CM_ SG_ 2332225183 M2P_ST_Master_slave_15 "主从集装箱架构状态";
CM_ SG_ 2332225183 M2P_Status_Fan_SW_15 "MBMU风扇控制继电器状态  ？MBMU控制电箱的风扇，确认内容//
2022/10/21
发送信号ScSTMS_FanCtrState";
CM_ SG_ 2332225183 M2P_Circuit_Breaker_15 "断路器状态，各个SBMU的高压上电状态";
CM_ SG_ 2332225183 M2P_NUM_OF_SlaveMBMU "系统中MBMU的总数量";
CM_ SG_ 2332225183 M2P_RackInhabitResult "电柜高压隔离结果";
CM_ SG_ 2332225183 M2P_STofSBMUAutoCoding_15 "SBMU地址自动编码状态";
CM_ SG_ 2332225183 M2P_LvSelfLock "MBMU电源自锁使能标志";
CM_ SG_ 2332225183 M2P_SbmuPwrOnFlg "SBMU供电完成标志";
CM_ SG_ 2332225183 M2P_InsulPwrOnFlg "IMM板供电完成标志";
CM_ SG_ 2332225183 M2P_HvOffReqFlg "高压继电器断开请求标志";
CM_ SG_ 2332225183 M2P_HvOnAllowFlg "低压上下电模块允许高压上电标志";
CM_ SG_ 2332225183 M2P_SBMULvoffAbnomal "SBMU异常下电标志";
CM_ SG_ 2332225183 M2P_LVPwrDFaultR "低压下电失败原因 ";
CM_ SG_ 2332225183 M2P_SysRunState "系统运行状态                                    ";
CM_ SG_ 2332225183 M2P_MIN_NUM_OF_ONLINE_SBMU "MBMU发送给 PC和ETH　最小运行给SBMU数量(预留，暂未实现)";
CM_ SG_ 2332225183 MBMU_Tank_Num_RelayOn "MBMU发送给 PCS 的在线电柜数量";
CM_ SG_ 2332225183 M2P_NUM_OF_SBMU "系统配置SBMU数量";
CM_ SG_ 2332225184 M2P_LifeSignal_16 "生命帧信号 0~15";
CM_ SG_ 2332225184 M2P_ST_Power_16 "系统上高压状态                                    ";
CM_ SG_ 2332225184 M2P_ST_Master_slave_16 "主从集装箱架构状态";
CM_ SG_ 2332225184 M2P_Status_Fan_SW_16 "MBMU风扇控制继电器状态  ？MBMU控制电箱的风扇，确认内容//
2022/10/21
发送信号ScSTMS_FanCtrState";
CM_ SG_ 2332225184 M2P_Circuit_Breaker_16 "断路器状态，各个SBMU的高压上电状态";
CM_ SG_ 2332225184 M2P_NUM_OF_SlaveMBMU "系统中MBMU的总数量";
CM_ SG_ 2332225184 M2P_RackInhabitResult "电柜高压隔离结果";
CM_ SG_ 2332225184 M2P_STofSBMUAutoCoding_16 "SBMU地址自动编码状态";
CM_ SG_ 2332225184 M2P_LvSelfLock "MBMU电源自锁使能标志";
CM_ SG_ 2332225184 M2P_SbmuPwrOnFlg "SBMU供电完成标志";
CM_ SG_ 2332225184 M2P_InsulPwrOnFlg "IMM板供电完成标志";
CM_ SG_ 2332225184 M2P_HvOffReqFlg "高压继电器断开请求标志";
CM_ SG_ 2332225184 M2P_HvOnAllowFlg "低压上下电模块允许高压上电标志";
CM_ SG_ 2332225184 M2P_SBMULvoffAbnomal "SBMU异常下电标志";
CM_ SG_ 2332225184 M2P_LVPwrDFaultR "低压下电失败原因 ";
CM_ SG_ 2332225184 M2P_SysRunState "系统运行状态                                    ";
CM_ SG_ 2332225184 M2P_MIN_NUM_OF_ONLINE_SBMU "MBMU发送给 PC和ETH　最小运行给SBMU数量(预留，暂未实现)";
CM_ SG_ 2332225184 MBMU_Tank_Num_RelayOn "MBMU发送给 PCS 的在线电柜数量";
CM_ SG_ 2332225184 M2P_NUM_OF_SBMU "系统配置SBMU数量";
CM_ SG_ 2332225185 M2P_LifeSignal_17 "生命帧信号 0~15";
CM_ SG_ 2332225185 M2P_ST_Power_17 "系统上高压状态                                    ";
CM_ SG_ 2332225185 M2P_ST_Master_slave_17 "主从集装箱架构状态";
CM_ SG_ 2332225185 M2P_Status_Fan_SW_17 "MBMU风扇控制继电器状态  ？MBMU控制电箱的风扇，确认内容//
2022/10/21
发送信号ScSTMS_FanCtrState";
CM_ SG_ 2332225185 M2P_Circuit_Breaker_17 "断路器状态，各个SBMU的高压上电状态";
CM_ SG_ 2332225185 M2P_NUM_OF_SlaveMBMU "系统中MBMU的总数量";
CM_ SG_ 2332225185 M2P_RackInhabitResult "电柜高压隔离结果";
CM_ SG_ 2332225185 M2P_STofSBMUAutoCoding_17 "SBMU地址自动编码状态";
CM_ SG_ 2332225185 M2P_LvSelfLock "MBMU电源自锁使能标志";
CM_ SG_ 2332225185 M2P_SbmuPwrOnFlg "SBMU供电完成标志";
CM_ SG_ 2332225185 M2P_InsulPwrOnFlg "IMM板供电完成标志";
CM_ SG_ 2332225185 M2P_HvOffReqFlg "高压继电器断开请求标志";
CM_ SG_ 2332225185 M2P_HvOnAllowFlg "低压上下电模块允许高压上电标志";
CM_ SG_ 2332225185 M2P_SBMULvoffAbnomal "SBMU异常下电标志";
CM_ SG_ 2332225185 M2P_LVPwrDFaultR "低压下电失败原因 ";
CM_ SG_ 2332225185 M2P_SysRunState "系统运行状态                                    ";
CM_ SG_ 2332225185 M2P_MIN_NUM_OF_ONLINE_SBMU "MBMU发送给 PC和ETH　最小运行给SBMU数量(预留，暂未实现)";
CM_ SG_ 2332225185 MBMU_Tank_Num_RelayOn "MBMU发送给 PCS 的在线电柜数量";
CM_ SG_ 2332225185 M2P_NUM_OF_SBMU "系统配置SBMU数量";
CM_ SG_ 2332225186 M2P_LifeSignal_18 "生命帧信号 0~15";
CM_ SG_ 2332225186 M2P_ST_Power_18 "系统上高压状态                                    ";
CM_ SG_ 2332225186 M2P_ST_Master_slave_18 "主从集装箱架构状态";
CM_ SG_ 2332225186 M2P_Status_Fan_SW_18 "MBMU风扇控制继电器状态  ？MBMU控制电箱的风扇，确认内容//
2022/10/21
发送信号ScSTMS_FanCtrState";
CM_ SG_ 2332225186 M2P_Circuit_Breaker_18 "断路器状态，各个SBMU的高压上电状态";
CM_ SG_ 2332225186 M2P_NUM_OF_SlaveMBMU "系统中MBMU的总数量";
CM_ SG_ 2332225186 M2P_RackInhabitResult "电柜高压隔离结果";
CM_ SG_ 2332225186 M2P_STofSBMUAutoCoding_18 "SBMU地址自动编码状态";
CM_ SG_ 2332225186 M2P_LvSelfLock "MBMU电源自锁使能标志";
CM_ SG_ 2332225186 M2P_SbmuPwrOnFlg "SBMU供电完成标志";
CM_ SG_ 2332225186 M2P_InsulPwrOnFlg "IMM板供电完成标志";
CM_ SG_ 2332225186 M2P_HvOffReqFlg "高压继电器断开请求标志";
CM_ SG_ 2332225186 M2P_HvOnAllowFlg "低压上下电模块允许高压上电标志";
CM_ SG_ 2332225186 M2P_SBMULvoffAbnomal "SBMU异常下电标志";
CM_ SG_ 2332225186 M2P_LVPwrDFaultR "低压下电失败原因 ";
CM_ SG_ 2332225186 M2P_SysRunState "系统运行状态                                    ";
CM_ SG_ 2332225186 M2P_MIN_NUM_OF_ONLINE_SBMU "MBMU发送给 PC和ETH　最小运行给SBMU数量(预留，暂未实现)";
CM_ SG_ 2332225186 MBMU_Tank_Num_RelayOn "MBMU发送给 PCS 的在线电柜数量";
CM_ SG_ 2332225186 M2P_NUM_OF_SBMU "系统配置SBMU数量";
CM_ SG_ 2332225187 M2P_LifeSignal_19 "生命帧信号 0~15";
CM_ SG_ 2332225187 M2P_ST_Power_19 "系统上高压状态                                    ";
CM_ SG_ 2332225187 M2P_ST_Master_slave_19 "主从集装箱架构状态";
CM_ SG_ 2332225187 M2P_Status_Fan_SW_19 "MBMU风扇控制继电器状态  ？MBMU控制电箱的风扇，确认内容//
2022/10/21
发送信号ScSTMS_FanCtrState";
CM_ SG_ 2332225187 M2P_Circuit_Breaker_19 "断路器状态，各个SBMU的高压上电状态";
CM_ SG_ 2332225187 M2P_NUM_OF_SlaveMBMU "系统中MBMU的总数量";
CM_ SG_ 2332225187 M2P_RackInhabitResult "电柜高压隔离结果";
CM_ SG_ 2332225187 M2P_STofSBMUAutoCoding_19 "SBMU地址自动编码状态";
CM_ SG_ 2332225187 M2P_LvSelfLock "MBMU电源自锁使能标志";
CM_ SG_ 2332225187 M2P_SbmuPwrOnFlg "SBMU供电完成标志";
CM_ SG_ 2332225187 M2P_InsulPwrOnFlg "IMM板供电完成标志";
CM_ SG_ 2332225187 M2P_HvOffReqFlg "高压继电器断开请求标志";
CM_ SG_ 2332225187 M2P_HvOnAllowFlg "低压上下电模块允许高压上电标志";
CM_ SG_ 2332225187 M2P_SBMULvoffAbnomal "SBMU异常下电标志";
CM_ SG_ 2332225187 M2P_LVPwrDFaultR "低压下电失败原因 ";
CM_ SG_ 2332225187 M2P_SysRunState "系统运行状态                                    ";
CM_ SG_ 2332225187 M2P_MIN_NUM_OF_ONLINE_SBMU "MBMU发送给 PC和ETH　最小运行给SBMU数量(预留，暂未实现)";
CM_ SG_ 2332225187 MBMU_Tank_Num_RelayOn "MBMU发送给 PCS 的在线电柜数量";
CM_ SG_ 2332225187 M2P_NUM_OF_SBMU "系统配置SBMU数量";
CM_ SG_ 2332225188 M2P_LifeSignal_20 "生命帧信号 0~15";
CM_ SG_ 2332225188 M2P_ST_Power_20 "系统上高压状态                                    ";
CM_ SG_ 2332225188 M2P_ST_Master_slave_20 "主从集装箱架构状态";
CM_ SG_ 2332225188 M2P_Status_Fan_SW_20 "MBMU风扇控制继电器状态  ？MBMU控制电箱的风扇，确认内容//
2022/10/21
发送信号ScSTMS_FanCtrState";
CM_ SG_ 2332225188 M2P_Circuit_Breaker_20 "断路器状态，各个SBMU的高压上电状态";
CM_ SG_ 2332225188 M2P_NUM_OF_SlaveMBMU "系统中MBMU的总数量";
CM_ SG_ 2332225188 M2P_RackInhabitResult "电柜高压隔离结果";
CM_ SG_ 2332225188 M2P_STofSBMUAutoCoding_20 "SBMU地址自动编码状态";
CM_ SG_ 2332225188 M2P_LvSelfLock "MBMU电源自锁使能标志";
CM_ SG_ 2332225188 M2P_SbmuPwrOnFlg "SBMU供电完成标志";
CM_ SG_ 2332225188 M2P_InsulPwrOnFlg "IMM板供电完成标志";
CM_ SG_ 2332225188 M2P_HvOffReqFlg "高压继电器断开请求标志";
CM_ SG_ 2332225188 M2P_HvOnAllowFlg "低压上下电模块允许高压上电标志";
CM_ SG_ 2332225188 M2P_SBMULvoffAbnomal "SBMU异常下电标志";
CM_ SG_ 2332225188 M2P_LVPwrDFaultR "低压下电失败原因 ";
CM_ SG_ 2332225188 M2P_SysRunState "系统运行状态                                    ";
CM_ SG_ 2332225188 M2P_MIN_NUM_OF_ONLINE_SBMU "MBMU发送给 PC和ETH　最小运行给SBMU数量(预留，暂未实现)";
CM_ SG_ 2332225188 MBMU_Tank_Num_RelayOn "MBMU发送给 PCS 的在线电柜数量";
CM_ SG_ 2332225188 M2P_NUM_OF_SBMU "系统配置SBMU数量";
CM_ SG_ 2332225189 M2P_LifeSignal_21 "生命帧信号 0~15";
CM_ SG_ 2332225189 M2P_ST_Power_21 "系统上高压状态                                    ";
CM_ SG_ 2332225189 M2P_ST_Master_slave_21 "主从集装箱架构状态";
CM_ SG_ 2332225189 M2P_Status_Fan_SW_21 "MBMU风扇控制继电器状态  ？MBMU控制电箱的风扇，确认内容//
2022/10/21
发送信号ScSTMS_FanCtrState";
CM_ SG_ 2332225189 M2P_Circuit_Breaker_21 "断路器状态，各个SBMU的高压上电状态";
CM_ SG_ 2332225189 M2P_NUM_OF_SlaveMBMU "系统中MBMU的总数量";
CM_ SG_ 2332225189 M2P_RackInhabitResult "电柜高压隔离结果";
CM_ SG_ 2332225189 M2P_STofSBMUAutoCoding_21 "SBMU地址自动编码状态";
CM_ SG_ 2332225189 M2P_LvSelfLock "MBMU电源自锁使能标志";
CM_ SG_ 2332225189 M2P_SbmuPwrOnFlg "SBMU供电完成标志";
CM_ SG_ 2332225189 M2P_InsulPwrOnFlg "IMM板供电完成标志";
CM_ SG_ 2332225189 M2P_HvOffReqFlg "高压继电器断开请求标志";
CM_ SG_ 2332225189 M2P_HvOnAllowFlg "低压上下电模块允许高压上电标志";
CM_ SG_ 2332225189 M2P_SBMULvoffAbnomal "SBMU异常下电标志";
CM_ SG_ 2332225189 M2P_LVPwrDFaultR "低压下电失败原因 ";
CM_ SG_ 2332225189 M2P_SysRunState "系统运行状态                                    ";
CM_ SG_ 2332225189 M2P_MIN_NUM_OF_ONLINE_SBMU "MBMU发送给 PC和ETH　最小运行给SBMU数量(预留，暂未实现)";
CM_ SG_ 2332225189 MBMU_Tank_Num_RelayOn "MBMU发送给 PCS 的在线电柜数量";
CM_ SG_ 2332225189 M2P_NUM_OF_SBMU "系统配置SBMU数量";
CM_ SG_ 2332225190 M2P_LifeSignal_22 "生命帧信号 0~15";
CM_ SG_ 2332225190 M2P_ST_Power_22 "系统上高压状态                                    ";
CM_ SG_ 2332225190 M2P_ST_Master_slave_22 "主从集装箱架构状态";
CM_ SG_ 2332225190 M2P_Status_Fan_SW_22 "MBMU风扇控制继电器状态  ？MBMU控制电箱的风扇，确认内容//
2022/10/21
发送信号ScSTMS_FanCtrState";
CM_ SG_ 2332225190 M2P_Circuit_Breaker_22 "断路器状态，各个SBMU的高压上电状态";
CM_ SG_ 2332225190 M2P_NUM_OF_SlaveMBMU "系统中MBMU的总数量";
CM_ SG_ 2332225190 M2P_RackInhabitResult "电柜高压隔离结果";
CM_ SG_ 2332225190 M2P_STofSBMUAutoCoding_22 "SBMU地址自动编码状态";
CM_ SG_ 2332225190 M2P_LvSelfLock "MBMU电源自锁使能标志";
CM_ SG_ 2332225190 M2P_SbmuPwrOnFlg "SBMU供电完成标志";
CM_ SG_ 2332225190 M2P_InsulPwrOnFlg "IMM板供电完成标志";
CM_ SG_ 2332225190 M2P_HvOffReqFlg "高压继电器断开请求标志";
CM_ SG_ 2332225190 M2P_HvOnAllowFlg "低压上下电模块允许高压上电标志";
CM_ SG_ 2332225190 M2P_SBMULvoffAbnomal "SBMU异常下电标志";
CM_ SG_ 2332225190 M2P_LVPwrDFaultR "低压下电失败原因 ";
CM_ SG_ 2332225190 M2P_SysRunState "系统运行状态                                    ";
CM_ SG_ 2332225190 M2P_MIN_NUM_OF_ONLINE_SBMU "MBMU发送给 PC和ETH　最小运行给SBMU数量(预留，暂未实现)";
CM_ SG_ 2332225190 MBMU_Tank_Num_RelayOn "MBMU发送给 PCS 的在线电柜数量";
CM_ SG_ 2332225190 M2P_NUM_OF_SBMU "系统配置SBMU数量";
CM_ SG_ 2332225191 M2P_LifeSignal_23 "生命帧信号 0~15";
CM_ SG_ 2332225191 M2P_ST_Power_23 "系统上高压状态                                    ";
CM_ SG_ 2332225191 M2P_ST_Master_slave_23 "主从集装箱架构状态";
CM_ SG_ 2332225191 M2P_Status_Fan_SW_23 "MBMU风扇控制继电器状态  ？MBMU控制电箱的风扇，确认内容//
2022/10/21
发送信号ScSTMS_FanCtrState";
CM_ SG_ 2332225191 M2P_Circuit_Breaker_23 "断路器状态，各个SBMU的高压上电状态";
CM_ SG_ 2332225191 M2P_NUM_OF_SlaveMBMU "系统中MBMU的总数量";
CM_ SG_ 2332225191 M2P_RackInhabitResult "电柜高压隔离结果";
CM_ SG_ 2332225191 M2P_STofSBMUAutoCoding_23 "SBMU地址自动编码状态";
CM_ SG_ 2332225191 M2P_LvSelfLock "MBMU电源自锁使能标志";
CM_ SG_ 2332225191 M2P_SbmuPwrOnFlg "SBMU供电完成标志";
CM_ SG_ 2332225191 M2P_InsulPwrOnFlg "IMM板供电完成标志";
CM_ SG_ 2332225191 M2P_HvOffReqFlg "高压继电器断开请求标志";
CM_ SG_ 2332225191 M2P_HvOnAllowFlg "低压上下电模块允许高压上电标志";
CM_ SG_ 2332225191 M2P_SBMULvoffAbnomal "SBMU异常下电标志";
CM_ SG_ 2332225191 M2P_LVPwrDFaultR "低压下电失败原因 ";
CM_ SG_ 2332225191 M2P_SysRunState "系统运行状态                                    ";
CM_ SG_ 2332225191 M2P_MIN_NUM_OF_ONLINE_SBMU "MBMU发送给 PC和ETH　最小运行给SBMU数量(预留，暂未实现)";
CM_ SG_ 2332225191 MBMU_Tank_Num_RelayOn "MBMU发送给 PCS 的在线电柜数量";
CM_ SG_ 2332225191 M2P_NUM_OF_SBMU "系统配置SBMU数量";
CM_ SG_ 2332225192 M2P_LifeSignal_24 "生命帧信号 0~15";
CM_ SG_ 2332225192 M2P_ST_Power_24 "系统上高压状态                                    ";
CM_ SG_ 2332225192 M2P_ST_Master_slave_24 "主从集装箱架构状态";
CM_ SG_ 2332225192 M2P_Status_Fan_SW_24 "MBMU风扇控制继电器状态  ？MBMU控制电箱的风扇，确认内容//
2022/10/21
发送信号ScSTMS_FanCtrState";
CM_ SG_ 2332225192 M2P_Circuit_Breaker_24 "断路器状态，各个SBMU的高压上电状态";
CM_ SG_ 2332225192 M2P_NUM_OF_SlaveMBMU "系统中MBMU的总数量";
CM_ SG_ 2332225192 M2P_RackInhabitResult "电柜高压隔离结果";
CM_ SG_ 2332225192 M2P_STofSBMUAutoCoding_24 "SBMU地址自动编码状态";
CM_ SG_ 2332225192 M2P_LvSelfLock "MBMU电源自锁使能标志";
CM_ SG_ 2332225192 M2P_SbmuPwrOnFlg "SBMU供电完成标志";
CM_ SG_ 2332225192 M2P_InsulPwrOnFlg "IMM板供电完成标志";
CM_ SG_ 2332225192 M2P_HvOffReqFlg "高压继电器断开请求标志";
CM_ SG_ 2332225192 M2P_HvOnAllowFlg "低压上下电模块允许高压上电标志";
CM_ SG_ 2332225192 M2P_SBMULvoffAbnomal "SBMU异常下电标志";
CM_ SG_ 2332225192 M2P_LVPwrDFaultR "低压下电失败原因 ";
CM_ SG_ 2332225192 M2P_SysRunState "系统运行状态                                    ";
CM_ SG_ 2332225192 M2P_MIN_NUM_OF_ONLINE_SBMU "MBMU发送给 PC和ETH　最小运行给SBMU数量(预留，暂未实现)";
CM_ SG_ 2332225192 MBMU_Tank_Num_RelayOn "MBMU发送给 PCS 的在线电柜数量";
CM_ SG_ 2332225192 M2P_NUM_OF_SBMU "系统配置SBMU数量";
CM_ SG_ 2332225193 M2P_LifeSignal_25 "生命帧信号 0~15";
CM_ SG_ 2332225193 M2P_ST_Power_25 "系统上高压状态                                    ";
CM_ SG_ 2332225193 M2P_ST_Master_slave_25 "主从集装箱架构状态";
CM_ SG_ 2332225193 M2P_Status_Fan_SW_25 "MBMU风扇控制继电器状态  ？MBMU控制电箱的风扇，确认内容//
2022/10/21
发送信号ScSTMS_FanCtrState";
CM_ SG_ 2332225193 M2P_Circuit_Breaker_25 "断路器状态，各个SBMU的高压上电状态";
CM_ SG_ 2332225193 M2P_NUM_OF_SlaveMBMU "系统中MBMU的总数量";
CM_ SG_ 2332225193 M2P_RackInhabitResult "电柜高压隔离结果";
CM_ SG_ 2332225193 M2P_STofSBMUAutoCoding_25 "SBMU地址自动编码状态";
CM_ SG_ 2332225193 M2P_LvSelfLock "MBMU电源自锁使能标志";
CM_ SG_ 2332225193 M2P_SbmuPwrOnFlg "SBMU供电完成标志";
CM_ SG_ 2332225193 M2P_InsulPwrOnFlg "IMM板供电完成标志";
CM_ SG_ 2332225193 M2P_HvOffReqFlg "高压继电器断开请求标志";
CM_ SG_ 2332225193 M2P_HvOnAllowFlg "低压上下电模块允许高压上电标志";
CM_ SG_ 2332225193 M2P_SBMULvoffAbnomal "SBMU异常下电标志";
CM_ SG_ 2332225193 M2P_LVPwrDFaultR "低压下电失败原因 ";
CM_ SG_ 2332225193 M2P_SysRunState "系统运行状态                                    ";
CM_ SG_ 2332225193 M2P_MIN_NUM_OF_ONLINE_SBMU "MBMU发送给 PC和ETH　最小运行给SBMU数量(预留，暂未实现)";
CM_ SG_ 2332225193 MBMU_Tank_Num_RelayOn "MBMU发送给 PCS 的在线电柜数量";
CM_ SG_ 2332225193 M2P_NUM_OF_SBMU "系统配置SBMU数量";
CM_ SG_ 2332225194 M2P_LifeSignal_26 "生命帧信号 0~15";
CM_ SG_ 2332225194 M2P_ST_Power_26 "系统上高压状态                                    ";
CM_ SG_ 2332225194 M2P_ST_Master_slave_26 "主从集装箱架构状态";
CM_ SG_ 2332225194 M2P_Status_Fan_SW_26 "MBMU风扇控制继电器状态  ？MBMU控制电箱的风扇，确认内容//
2022/10/21
发送信号ScSTMS_FanCtrState";
CM_ SG_ 2332225194 M2P_Circuit_Breaker_26 "断路器状态，各个SBMU的高压上电状态";
CM_ SG_ 2332225194 M2P_NUM_OF_SlaveMBMU "系统中MBMU的总数量";
CM_ SG_ 2332225194 M2P_RackInhabitResult "电柜高压隔离结果";
CM_ SG_ 2332225194 M2P_STofSBMUAutoCoding_26 "SBMU地址自动编码状态";
CM_ SG_ 2332225194 M2P_LvSelfLock "MBMU电源自锁使能标志";
CM_ SG_ 2332225194 M2P_SbmuPwrOnFlg "SBMU供电完成标志";
CM_ SG_ 2332225194 M2P_InsulPwrOnFlg "IMM板供电完成标志";
CM_ SG_ 2332225194 M2P_HvOffReqFlg "高压继电器断开请求标志";
CM_ SG_ 2332225194 M2P_HvOnAllowFlg "低压上下电模块允许高压上电标志";
CM_ SG_ 2332225194 M2P_SBMULvoffAbnomal "SBMU异常下电标志";
CM_ SG_ 2332225194 M2P_LVPwrDFaultR "低压下电失败原因 ";
CM_ SG_ 2332225194 M2P_SysRunState "系统运行状态                                    ";
CM_ SG_ 2332225194 M2P_MIN_NUM_OF_ONLINE_SBMU "MBMU发送给 PC和ETH　最小运行给SBMU数量(预留，暂未实现)";
CM_ SG_ 2332225194 MBMU_Tank_Num_RelayOn "MBMU发送给 PCS 的在线电柜数量";
CM_ SG_ 2332225194 M2P_NUM_OF_SBMU "系统配置SBMU数量";
CM_ SG_ 2332225195 M2P_LifeSignal_27 "生命帧信号 0~15";
CM_ SG_ 2332225195 M2P_ST_Power_27 "系统上高压状态                                    ";
CM_ SG_ 2332225195 M2P_ST_Master_slave_27 "主从集装箱架构状态";
CM_ SG_ 2332225195 M2P_Status_Fan_SW_27 "MBMU风扇控制继电器状态  ？MBMU控制电箱的风扇，确认内容//
2022/10/21
发送信号ScSTMS_FanCtrState";
CM_ SG_ 2332225195 M2P_Circuit_Breaker_27 "断路器状态，各个SBMU的高压上电状态";
CM_ SG_ 2332225195 M2P_NUM_OF_SlaveMBMU "系统中MBMU的总数量";
CM_ SG_ 2332225195 M2P_RackInhabitResult "电柜高压隔离结果";
CM_ SG_ 2332225195 M2P_STofSBMUAutoCoding_27 "SBMU地址自动编码状态";
CM_ SG_ 2332225195 M2P_LvSelfLock "MBMU电源自锁使能标志";
CM_ SG_ 2332225195 M2P_SbmuPwrOnFlg "SBMU供电完成标志";
CM_ SG_ 2332225195 M2P_InsulPwrOnFlg "IMM板供电完成标志";
CM_ SG_ 2332225195 M2P_HvOffReqFlg "高压继电器断开请求标志";
CM_ SG_ 2332225195 M2P_HvOnAllowFlg "低压上下电模块允许高压上电标志";
CM_ SG_ 2332225195 M2P_SBMULvoffAbnomal "SBMU异常下电标志";
CM_ SG_ 2332225195 M2P_LVPwrDFaultR "低压下电失败原因 ";
CM_ SG_ 2332225195 M2P_SysRunState "系统运行状态                                    ";
CM_ SG_ 2332225195 M2P_MIN_NUM_OF_ONLINE_SBMU "MBMU发送给 PC和ETH　最小运行给SBMU数量(预留，暂未实现)";
CM_ SG_ 2332225195 MBMU_Tank_Num_RelayOn "MBMU发送给 PCS 的在线电柜数量";
CM_ SG_ 2332225195 M2P_NUM_OF_SBMU "系统配置SBMU数量";
CM_ SG_ 2332225196 M2P_LifeSignal_28 "生命帧信号 0~15";
CM_ SG_ 2332225196 M2P_ST_Power_28 "系统上高压状态                                    ";
CM_ SG_ 2332225196 M2P_ST_Master_slave_28 "主从集装箱架构状态";
CM_ SG_ 2332225196 M2P_Status_Fan_SW_28 "MBMU风扇控制继电器状态  ？MBMU控制电箱的风扇，确认内容//
2022/10/21
发送信号ScSTMS_FanCtrState";
CM_ SG_ 2332225196 M2P_Circuit_Breaker_28 "断路器状态，各个SBMU的高压上电状态";
CM_ SG_ 2332225196 M2P_NUM_OF_SlaveMBMU "系统中MBMU的总数量";
CM_ SG_ 2332225196 M2P_RackInhabitResult "电柜高压隔离结果";
CM_ SG_ 2332225196 M2P_STofSBMUAutoCoding_28 "SBMU地址自动编码状态";
CM_ SG_ 2332225196 M2P_LvSelfLock "MBMU电源自锁使能标志";
CM_ SG_ 2332225196 M2P_SbmuPwrOnFlg "SBMU供电完成标志";
CM_ SG_ 2332225196 M2P_InsulPwrOnFlg "IMM板供电完成标志";
CM_ SG_ 2332225196 M2P_HvOffReqFlg "高压继电器断开请求标志";
CM_ SG_ 2332225196 M2P_HvOnAllowFlg "低压上下电模块允许高压上电标志";
CM_ SG_ 2332225196 M2P_SBMULvoffAbnomal "SBMU异常下电标志";
CM_ SG_ 2332225196 M2P_LVPwrDFaultR "低压下电失败原因 ";
CM_ SG_ 2332225196 M2P_SysRunState "系统运行状态                                    ";
CM_ SG_ 2332225196 M2P_MIN_NUM_OF_ONLINE_SBMU "MBMU发送给 PC和ETH　最小运行给SBMU数量(预留，暂未实现)";
CM_ SG_ 2332225196 MBMU_Tank_Num_RelayOn "MBMU发送给 PCS 的在线电柜数量";
CM_ SG_ 2332225196 M2P_NUM_OF_SBMU "系统配置SBMU数量";
CM_ SG_ 2332225197 M2P_LifeSignal_29 "生命帧信号 0~15";
CM_ SG_ 2332225197 M2P_ST_Power_29 "系统上高压状态                                    ";
CM_ SG_ 2332225197 M2P_ST_Master_slave_29 "主从集装箱架构状态";
CM_ SG_ 2332225197 M2P_Status_Fan_SW_29 "MBMU风扇控制继电器状态  ？MBMU控制电箱的风扇，确认内容//
2022/10/21
发送信号ScSTMS_FanCtrState";
CM_ SG_ 2332225197 M2P_Circuit_Breaker_29 "断路器状态，各个SBMU的高压上电状态";
CM_ SG_ 2332225197 M2P_NUM_OF_SlaveMBMU "系统中MBMU的总数量";
CM_ SG_ 2332225197 M2P_RackInhabitResult "电柜高压隔离结果";
CM_ SG_ 2332225197 M2P_STofSBMUAutoCoding_29 "SBMU地址自动编码状态";
CM_ SG_ 2332225197 M2P_LvSelfLock "MBMU电源自锁使能标志";
CM_ SG_ 2332225197 M2P_SbmuPwrOnFlg "SBMU供电完成标志";
CM_ SG_ 2332225197 M2P_InsulPwrOnFlg "IMM板供电完成标志";
CM_ SG_ 2332225197 M2P_HvOffReqFlg "高压继电器断开请求标志";
CM_ SG_ 2332225197 M2P_HvOnAllowFlg "低压上下电模块允许高压上电标志";
CM_ SG_ 2332225197 M2P_SBMULvoffAbnomal "SBMU异常下电标志";
CM_ SG_ 2332225197 M2P_LVPwrDFaultR "低压下电失败原因 ";
CM_ SG_ 2332225197 M2P_SysRunState "系统运行状态                                    ";
CM_ SG_ 2332225197 M2P_MIN_NUM_OF_ONLINE_SBMU "MBMU发送给 PC和ETH　最小运行给SBMU数量(预留，暂未实现)";
CM_ SG_ 2332225197 MBMU_Tank_Num_RelayOn "MBMU发送给 PCS 的在线电柜数量";
CM_ SG_ 2332225197 M2P_NUM_OF_SBMU "系统配置SBMU数量";
CM_ SG_ 2332225198 M2P_LifeSignal_30 "生命帧信号 0~15";
CM_ SG_ 2332225198 M2P_ST_Power_30 "系统上高压状态                                    ";
CM_ SG_ 2332225198 M2P_ST_Master_slave_30 "主从集装箱架构状态";
CM_ SG_ 2332225198 M2P_Status_Fan_SW_30 "MBMU风扇控制继电器状态  ？MBMU控制电箱的风扇，确认内容//
2022/10/21
发送信号ScSTMS_FanCtrState";
CM_ SG_ 2332225198 M2P_Circuit_Breaker_30 "断路器状态，各个SBMU的高压上电状态";
CM_ SG_ 2332225198 M2P_NUM_OF_SlaveMBMU "系统中MBMU的总数量";
CM_ SG_ 2332225198 M2P_RackInhabitResult "电柜高压隔离结果";
CM_ SG_ 2332225198 M2P_STofSBMUAutoCoding_30 "SBMU地址自动编码状态";
CM_ SG_ 2332225198 M2P_LvSelfLock "MBMU电源自锁使能标志";
CM_ SG_ 2332225198 M2P_SbmuPwrOnFlg "SBMU供电完成标志";
CM_ SG_ 2332225198 M2P_InsulPwrOnFlg "IMM板供电完成标志";
CM_ SG_ 2332225198 M2P_HvOffReqFlg "高压继电器断开请求标志";
CM_ SG_ 2332225198 M2P_HvOnAllowFlg "低压上下电模块允许高压上电标志";
CM_ SG_ 2332225198 M2P_SBMULvoffAbnomal "SBMU异常下电标志";
CM_ SG_ 2332225198 M2P_LVPwrDFaultR "低压下电失败原因 ";
CM_ SG_ 2332225198 M2P_SysRunState "系统运行状态                                    ";
CM_ SG_ 2332225198 M2P_MIN_NUM_OF_ONLINE_SBMU "MBMU发送给 PC和ETH　最小运行给SBMU数量(预留，暂未实现)";
CM_ SG_ 2332225198 MBMU_Tank_Num_RelayOn "MBMU发送给 PCS 的在线电柜数量";
CM_ SG_ 2332225198 M2P_NUM_OF_SBMU "系统配置SBMU数量";
CM_ SG_ 2332225199 M2P_LifeSignal_31 "生命帧信号 0~15";
CM_ SG_ 2332225199 M2P_ST_Power_31 "系统上高压状态                                    ";
CM_ SG_ 2332225199 M2P_ST_Master_slave_31 "主从集装箱架构状态";
CM_ SG_ 2332225199 M2P_Status_Fan_SW_31 "MBMU风扇控制继电器状态  ？MBMU控制电箱的风扇，确认内容//
2022/10/21
发送信号ScSTMS_FanCtrState";
CM_ SG_ 2332225199 M2P_Circuit_Breaker_31 "断路器状态，各个SBMU的高压上电状态";
CM_ SG_ 2332225199 M2P_NUM_OF_SlaveMBMU "系统中MBMU的总数量";
CM_ SG_ 2332225199 M2P_RackInhabitResult "电柜高压隔离结果";
CM_ SG_ 2332225199 M2P_STofSBMUAutoCoding_31 "SBMU地址自动编码状态";
CM_ SG_ 2332225199 M2P_LvSelfLock "MBMU电源自锁使能标志";
CM_ SG_ 2332225199 M2P_SbmuPwrOnFlg "SBMU供电完成标志";
CM_ SG_ 2332225199 M2P_InsulPwrOnFlg "IMM板供电完成标志";
CM_ SG_ 2332225199 M2P_HvOffReqFlg "高压继电器断开请求标志";
CM_ SG_ 2332225199 M2P_HvOnAllowFlg "低压上下电模块允许高压上电标志";
CM_ SG_ 2332225199 M2P_SBMULvoffAbnomal "SBMU异常下电标志";
CM_ SG_ 2332225199 M2P_LVPwrDFaultR "低压下电失败原因 ";
CM_ SG_ 2332225199 M2P_SysRunState "系统运行状态                                    ";
CM_ SG_ 2332225199 M2P_MIN_NUM_OF_ONLINE_SBMU "MBMU发送给 PC和ETH　最小运行给SBMU数量(预留，暂未实现)";
CM_ SG_ 2332225199 MBMU_Tank_Num_RelayOn "MBMU发送给 PCS 的在线电柜数量";
CM_ SG_ 2332225199 M2P_NUM_OF_SBMU "系统配置SBMU数量";
CM_ SG_ 2332290705 M2P_PermitMaxCharge_I_01 "最大允许充电电流";
CM_ SG_ 2332290705 M2P_PermitMaxDisCharge_I_01 "最大允许放电电流";
CM_ SG_ 2332290705 M2P_Evn_T1_01 "MBMU环境温度1";
CM_ SG_ 2332290705 M2P_Evn_T2_01 "MBMU环境温度2";
CM_ SG_ 2332290705 M2P_Evn_T3_01 "MBMU环境温度3";
CM_ SG_ 2332290705 M2P_Evn_Humidity_01 "MBMU环境湿度";
CM_ SG_ 2332290706 M2P_PermitMaxCharge_I_02 "最大允许充电电流";
CM_ SG_ 2332290706 M2P_PermitMaxDisCharge_I_02 "最大允许放电电流";
CM_ SG_ 2332290706 M2P_Evn_T1_02 "MBMU环境温度1";
CM_ SG_ 2332290706 M2P_Evn_T2_02 "MBMU环境温度2";
CM_ SG_ 2332290706 M2P_Evn_T3_02 "MBMU环境温度3";
CM_ SG_ 2332290706 M2P_Evn_Humidity_02 "MBMU环境湿度";
CM_ SG_ 2332290707 M2P_PermitMaxCharge_I_03 "最大允许充电电流";
CM_ SG_ 2332290707 M2P_PermitMaxDisCharge_I_03 "最大允许放电电流";
CM_ SG_ 2332290707 M2P_Evn_T1_03 "MBMU环境温度1";
CM_ SG_ 2332290707 M2P_Evn_T2_03 "MBMU环境温度2";
CM_ SG_ 2332290707 M2P_Evn_T3_03 "MBMU环境温度3";
CM_ SG_ 2332290707 M2P_Evn_Humidity_03 "MBMU环境湿度";
CM_ SG_ 2332290708 M2P_PermitMaxCharge_I_04 "最大允许充电电流";
CM_ SG_ 2332290708 M2P_PermitMaxDisCharge_I_04 "最大允许放电电流";
CM_ SG_ 2332290708 M2P_Evn_T1_04 "MBMU环境温度1";
CM_ SG_ 2332290708 M2P_Evn_T2_04 "MBMU环境温度2";
CM_ SG_ 2332290708 M2P_Evn_T3_04 "MBMU环境温度3";
CM_ SG_ 2332290708 M2P_Evn_Humidity_04 "MBMU环境湿度";
CM_ SG_ 2332290709 M2P_PermitMaxCharge_I_05 "最大允许充电电流";
CM_ SG_ 2332290709 M2P_PermitMaxDisCharge_I_05 "最大允许放电电流";
CM_ SG_ 2332290709 M2P_Evn_T1_05 "MBMU环境温度1";
CM_ SG_ 2332290709 M2P_Evn_T2_05 "MBMU环境温度2";
CM_ SG_ 2332290709 M2P_Evn_T3_05 "MBMU环境温度3";
CM_ SG_ 2332290709 M2P_Evn_Humidity_05 "MBMU环境湿度";
CM_ SG_ 2332290710 M2P_PermitMaxCharge_I_06 "最大允许充电电流";
CM_ SG_ 2332290710 M2P_PermitMaxDisCharge_I_06 "最大允许放电电流";
CM_ SG_ 2332290710 M2P_Evn_T1_06 "MBMU环境温度1";
CM_ SG_ 2332290710 M2P_Evn_T2_06 "MBMU环境温度2";
CM_ SG_ 2332290710 M2P_Evn_T3_06 "MBMU环境温度3";
CM_ SG_ 2332290710 M2P_Evn_Humidity_06 "MBMU环境湿度";
CM_ SG_ 2332290711 M2P_PermitMaxCharge_I_07 "最大允许充电电流";
CM_ SG_ 2332290711 M2P_PermitMaxDisCharge_I_07 "最大允许放电电流";
CM_ SG_ 2332290711 M2P_Evn_T1_07 "MBMU环境温度1";
CM_ SG_ 2332290711 M2P_Evn_T2_07 "MBMU环境温度2";
CM_ SG_ 2332290711 M2P_Evn_T3_07 "MBMU环境温度3";
CM_ SG_ 2332290711 M2P_Evn_Humidity_07 "MBMU环境湿度";
CM_ SG_ 2332290712 M2P_PermitMaxCharge_I_08 "最大允许充电电流";
CM_ SG_ 2332290712 M2P_PermitMaxDisCharge_I_08 "最大允许放电电流";
CM_ SG_ 2332290712 M2P_Evn_T1_08 "MBMU环境温度1";
CM_ SG_ 2332290712 M2P_Evn_T2_08 "MBMU环境温度2";
CM_ SG_ 2332290712 M2P_Evn_T3_08 "MBMU环境温度3";
CM_ SG_ 2332290712 M2P_Evn_Humidity_08 "MBMU环境湿度";
CM_ SG_ 2332290713 M2P_PermitMaxCharge_I_09 "最大允许充电电流";
CM_ SG_ 2332290713 M2P_PermitMaxDisCharge_I_09 "最大允许放电电流";
CM_ SG_ 2332290713 M2P_Evn_T1_09 "MBMU环境温度1";
CM_ SG_ 2332290713 M2P_Evn_T2_09 "MBMU环境温度2";
CM_ SG_ 2332290713 M2P_Evn_T3_09 "MBMU环境温度3";
CM_ SG_ 2332290713 M2P_Evn_Humidity_09 "MBMU环境湿度";
CM_ SG_ 2332290714 M2P_PermitMaxCharge_I_10 "最大允许充电电流";
CM_ SG_ 2332290714 M2P_PermitMaxDisCharge_I_10 "最大允许放电电流";
CM_ SG_ 2332290714 M2P_Evn_T1_10 "MBMU环境温度1";
CM_ SG_ 2332290714 M2P_Evn_T2_10 "MBMU环境温度2";
CM_ SG_ 2332290714 M2P_Evn_T3_10 "MBMU环境温度3";
CM_ SG_ 2332290714 M2P_Evn_Humidity_10 "MBMU环境湿度";
CM_ SG_ 2332290715 M2P_PermitMaxCharge_I_11 "最大允许充电电流";
CM_ SG_ 2332290715 M2P_PermitMaxDisCharge_I_11 "最大允许放电电流";
CM_ SG_ 2332290715 M2P_Evn_T1_11 "MBMU环境温度1";
CM_ SG_ 2332290715 M2P_Evn_T2_11 "MBMU环境温度2";
CM_ SG_ 2332290715 M2P_Evn_T3_11 "MBMU环境温度3";
CM_ SG_ 2332290715 M2P_Evn_Humidity_11 "MBMU环境湿度";
CM_ SG_ 2332290716 M2P_PermitMaxCharge_I_12 "最大允许充电电流";
CM_ SG_ 2332290716 M2P_PermitMaxDisCharge_I_12 "最大允许放电电流";
CM_ SG_ 2332290716 M2P_Evn_T1_12 "MBMU环境温度1";
CM_ SG_ 2332290716 M2P_Evn_T2_12 "MBMU环境温度2";
CM_ SG_ 2332290716 M2P_Evn_T3_12 "MBMU环境温度3";
CM_ SG_ 2332290716 M2P_Evn_Humidity_12 "MBMU环境湿度";
CM_ SG_ 2332290717 M2P_PermitMaxCharge_I_13 "最大允许充电电流";
CM_ SG_ 2332290717 M2P_PermitMaxDisCharge_I_13 "最大允许放电电流";
CM_ SG_ 2332290717 M2P_Evn_T1_13 "MBMU环境温度1";
CM_ SG_ 2332290717 M2P_Evn_T2_13 "MBMU环境温度2";
CM_ SG_ 2332290717 M2P_Evn_T3_13 "MBMU环境温度3";
CM_ SG_ 2332290717 M2P_Evn_Humidity_13 "MBMU环境湿度";
CM_ SG_ 2332290718 M2P_PermitMaxCharge_I_14 "最大允许充电电流";
CM_ SG_ 2332290718 M2P_PermitMaxDisCharge_I_14 "最大允许放电电流";
CM_ SG_ 2332290718 M2P_Evn_T1_14 "MBMU环境温度1";
CM_ SG_ 2332290718 M2P_Evn_T2_14 "MBMU环境温度2";
CM_ SG_ 2332290718 M2P_Evn_T3_14 "MBMU环境温度3";
CM_ SG_ 2332290718 M2P_Evn_Humidity_14 "MBMU环境湿度";
CM_ SG_ 2332290719 M2P_PermitMaxCharge_I_15 "最大允许充电电流";
CM_ SG_ 2332290719 M2P_PermitMaxDisCharge_I_15 "最大允许放电电流";
CM_ SG_ 2332290719 M2P_Evn_T1_15 "MBMU环境温度1";
CM_ SG_ 2332290719 M2P_Evn_T2_15 "MBMU环境温度2";
CM_ SG_ 2332290719 M2P_Evn_T3_15 "MBMU环境温度3";
CM_ SG_ 2332290719 M2P_Evn_Humidity_15 "MBMU环境湿度";
CM_ SG_ 2332290720 M2P_PermitMaxCharge_I_16 "最大允许充电电流";
CM_ SG_ 2332290720 M2P_PermitMaxDisCharge_I_16 "最大允许放电电流";
CM_ SG_ 2332290720 M2P_Evn_T1_16 "MBMU环境温度1";
CM_ SG_ 2332290720 M2P_Evn_T2_16 "MBMU环境温度2";
CM_ SG_ 2332290720 M2P_Evn_T3_16 "MBMU环境温度3";
CM_ SG_ 2332290720 M2P_Evn_Humidity_16 "MBMU环境湿度";
CM_ SG_ 2332290721 M2P_PermitMaxCharge_I_17 "最大允许充电电流";
CM_ SG_ 2332290721 M2P_PermitMaxDisCharge_I_17 "最大允许放电电流";
CM_ SG_ 2332290721 M2P_Evn_T1_17 "MBMU环境温度1";
CM_ SG_ 2332290721 M2P_Evn_T2_17 "MBMU环境温度2";
CM_ SG_ 2332290721 M2P_Evn_T3_17 "MBMU环境温度3";
CM_ SG_ 2332290721 M2P_Evn_Humidity_17 "MBMU环境湿度";
CM_ SG_ 2332290722 M2P_PermitMaxCharge_I_18 "最大允许充电电流";
CM_ SG_ 2332290722 M2P_PermitMaxDisCharge_I_18 "最大允许放电电流";
CM_ SG_ 2332290722 M2P_Evn_T1_18 "MBMU环境温度1";
CM_ SG_ 2332290722 M2P_Evn_T2_18 "MBMU环境温度2";
CM_ SG_ 2332290722 M2P_Evn_T3_18 "MBMU环境温度3";
CM_ SG_ 2332290722 M2P_Evn_Humidity_18 "MBMU环境湿度";
CM_ SG_ 2332290723 M2P_PermitMaxCharge_I_19 "最大允许充电电流";
CM_ SG_ 2332290723 M2P_PermitMaxDisCharge_I_19 "最大允许放电电流";
CM_ SG_ 2332290723 M2P_Evn_T1_19 "MBMU环境温度1";
CM_ SG_ 2332290723 M2P_Evn_T2_19 "MBMU环境温度2";
CM_ SG_ 2332290723 M2P_Evn_T3_19 "MBMU环境温度3";
CM_ SG_ 2332290723 M2P_Evn_Humidity_19 "MBMU环境湿度";
CM_ SG_ 2332290724 M2P_PermitMaxCharge_I_20 "最大允许充电电流";
CM_ SG_ 2332290724 M2P_PermitMaxDisCharge_I_20 "最大允许放电电流";
CM_ SG_ 2332290724 M2P_Evn_T1_20 "MBMU环境温度1";
CM_ SG_ 2332290724 M2P_Evn_T2_20 "MBMU环境温度2";
CM_ SG_ 2332290724 M2P_Evn_T3_20 "MBMU环境温度3";
CM_ SG_ 2332290724 M2P_Evn_Humidity_20 "MBMU环境湿度";
CM_ SG_ 2332290725 M2P_PermitMaxCharge_I_21 "最大允许充电电流";
CM_ SG_ 2332290725 M2P_PermitMaxDisCharge_I_21 "最大允许放电电流";
CM_ SG_ 2332290725 M2P_Evn_T1_21 "MBMU环境温度1";
CM_ SG_ 2332290725 M2P_Evn_T2_21 "MBMU环境温度2";
CM_ SG_ 2332290725 M2P_Evn_T3_21 "MBMU环境温度3";
CM_ SG_ 2332290725 M2P_Evn_Humidity_21 "MBMU环境湿度";
CM_ SG_ 2332290726 M2P_PermitMaxCharge_I_22 "最大允许充电电流";
CM_ SG_ 2332290726 M2P_PermitMaxDisCharge_I_22 "最大允许放电电流";
CM_ SG_ 2332290726 M2P_Evn_T1_22 "MBMU环境温度1";
CM_ SG_ 2332290726 M2P_Evn_T2_22 "MBMU环境温度2";
CM_ SG_ 2332290726 M2P_Evn_T3_22 "MBMU环境温度3";
CM_ SG_ 2332290726 M2P_Evn_Humidity_22 "MBMU环境湿度";
CM_ SG_ 2332290727 M2P_PermitMaxCharge_I_23 "最大允许充电电流";
CM_ SG_ 2332290727 M2P_PermitMaxDisCharge_I_23 "最大允许放电电流";
CM_ SG_ 2332290727 M2P_Evn_T1_23 "MBMU环境温度1";
CM_ SG_ 2332290727 M2P_Evn_T2_23 "MBMU环境温度2";
CM_ SG_ 2332290727 M2P_Evn_T3_23 "MBMU环境温度3";
CM_ SG_ 2332290727 M2P_Evn_Humidity_23 "MBMU环境湿度";
CM_ SG_ 2332290728 M2P_PermitMaxCharge_I_24 "最大允许充电电流";
CM_ SG_ 2332290728 M2P_PermitMaxDisCharge_I_24 "最大允许放电电流";
CM_ SG_ 2332290728 M2P_Evn_T1_24 "MBMU环境温度1";
CM_ SG_ 2332290728 M2P_Evn_T2_24 "MBMU环境温度2";
CM_ SG_ 2332290728 M2P_Evn_T3_24 "MBMU环境温度3";
CM_ SG_ 2332290728 M2P_Evn_Humidity_24 "MBMU环境湿度";
CM_ SG_ 2332290729 M2P_PermitMaxCharge_I_25 "最大允许充电电流";
CM_ SG_ 2332290729 M2P_PermitMaxDisCharge_I_25 "最大允许放电电流";
CM_ SG_ 2332290729 M2P_Evn_T1_25 "MBMU环境温度1";
CM_ SG_ 2332290729 M2P_Evn_T2_25 "MBMU环境温度2";
CM_ SG_ 2332290729 M2P_Evn_T3_25 "MBMU环境温度3";
CM_ SG_ 2332290729 M2P_Evn_Humidity_25 "MBMU环境湿度";
CM_ SG_ 2332290730 M2P_PermitMaxCharge_I_26 "最大允许充电电流";
CM_ SG_ 2332290730 M2P_PermitMaxDisCharge_I_26 "最大允许放电电流";
CM_ SG_ 2332290730 M2P_Evn_T1_26 "MBMU环境温度1";
CM_ SG_ 2332290730 M2P_Evn_T2_26 "MBMU环境温度2";
CM_ SG_ 2332290730 M2P_Evn_T3_26 "MBMU环境温度3";
CM_ SG_ 2332290730 M2P_Evn_Humidity_26 "MBMU环境湿度";
VAL_ 2332159633 M2P_Measure_Vol_01 65535 "Invalid" ;
VAL_ 2332159633 M2P_Current_01 65535 "Invalid" ;
VAL_ 2332159633 M2P_SOH_01 1023 "Invalid" ;
VAL_ 2332159633 M2P_RSOC_01 1023 "Invalid" ;
VAL_ 2332159633 M2P_DSOC_01 1023 "Invalid" ;
VAL_ 2332159633 CMD_of_Closed_Loop_01 0 "关闭" 1 "开启" ;
VAL_ 2332159633 SOCDiffHighFlg 0 "normal" 1 "alarm" ;
VAL_ 2332159634 M2P_Measure_Vol_02 65535 "Invalid" ;
VAL_ 2332159634 M2P_Current_02 65535 "Invalid" ;
VAL_ 2332159634 M2P_SOH_02 1023 "Invalid" ;
VAL_ 2332159634 M2P_RSOC_02 1023 "Invalid" ;
VAL_ 2332159634 M2P_DSOC_02 1023 "Invalid" ;
VAL_ 2332159634 CMD_of_Closed_Loop_02 0 "关闭" 1 "开启" ;
VAL_ 2332159634 SOCDiffHighFlg 0 "normal" 1 "alarm" ;
VAL_ 2332159635 M2P_Measure_Vol_03 65535 "Invalid" ;
VAL_ 2332159635 M2P_Current_03 65535 "Invalid" ;
VAL_ 2332159635 M2P_SOH_03 1023 "Invalid" ;
VAL_ 2332159635 M2P_RSOC_03 1023 "Invalid" ;
VAL_ 2332159635 M2P_DSOC_03 1023 "Invalid" ;
VAL_ 2332159635 CMD_of_Closed_Loop_03 0 "关闭" 1 "开启" ;
VAL_ 2332159635 SOCDiffHighFlg 0 "normal" 1 "alarm" ;
VAL_ 2332159636 M2P_Measure_Vol_04 65535 "Invalid" ;
VAL_ 2332159636 M2P_Current_04 65535 "Invalid" ;
VAL_ 2332159636 M2P_SOH_04 1023 "Invalid" ;
VAL_ 2332159636 M2P_RSOC_04 1023 "Invalid" ;
VAL_ 2332159636 M2P_DSOC_04 1023 "Invalid" ;
VAL_ 2332159636 CMD_of_Closed_Loop_04 0 "关闭" 1 "开启" ;
VAL_ 2332159636 SOCDiffHighFlg 0 "normal" 1 "alarm" ;
VAL_ 2332159637 M2P_Measure_Vol_05 65535 "Invalid" ;
VAL_ 2332159637 M2P_Current_05 65535 "Invalid" ;
VAL_ 2332159637 M2P_SOH_05 1023 "Invalid" ;
VAL_ 2332159637 M2P_RSOC_05 1023 "Invalid" ;
VAL_ 2332159637 M2P_DSOC_05 1023 "Invalid" ;
VAL_ 2332159637 CMD_of_Closed_Loop_05 0 "关闭" 1 "开启" ;
VAL_ 2332159637 SOCDiffHighFlg 0 "normal" 1 "alarm" ;
VAL_ 2332159638 M2P_Measure_Vol_06 65535 "Invalid" ;
VAL_ 2332159638 M2P_Current_06 65535 "Invalid" ;
VAL_ 2332159638 M2P_SOH_06 1023 "Invalid" ;
VAL_ 2332159638 M2P_RSOC_06 1023 "Invalid" ;
VAL_ 2332159638 M2P_DSOC_06 1023 "Invalid" ;
VAL_ 2332159638 CMD_of_Closed_Loop_06 0 "关闭" 1 "开启" ;
VAL_ 2332159638 SOCDiffHighFlg 0 "normal" 1 "alarm" ;
VAL_ 2332159639 M2P_Measure_Vol_07 65535 "Invalid" ;
VAL_ 2332159639 M2P_Current_07 65535 "Invalid" ;
VAL_ 2332159639 M2P_SOH_07 1023 "Invalid" ;
VAL_ 2332159639 M2P_RSOC_07 1023 "Invalid" ;
VAL_ 2332159639 M2P_DSOC_07 1023 "Invalid" ;
VAL_ 2332159639 CMD_of_Closed_Loop_07 0 "关闭" 1 "开启" ;
VAL_ 2332159639 SOCDiffHighFlg 0 "normal" 1 "alarm" ;
VAL_ 2332159640 M2P_Measure_Vol_08 65535 "Invalid" ;
VAL_ 2332159640 M2P_Current_08 65535 "Invalid" ;
VAL_ 2332159640 M2P_SOH_08 1023 "Invalid" ;
VAL_ 2332159640 M2P_RSOC_08 1023 "Invalid" ;
VAL_ 2332159640 M2P_DSOC_08 1023 "Invalid" ;
VAL_ 2332159640 CMD_of_Closed_Loop_08 0 "关闭" 1 "开启" ;
VAL_ 2332159640 SOCDiffHighFlg 0 "normal" 1 "alarm" ;
VAL_ 2332159641 M2P_Measure_Vol_09 65535 "Invalid" ;
VAL_ 2332159641 M2P_Current_09 65535 "Invalid" ;
VAL_ 2332159641 M2P_SOH_09 1023 "Invalid" ;
VAL_ 2332159641 M2P_RSOC_09 1023 "Invalid" ;
VAL_ 2332159641 M2P_DSOC_09 1023 "Invalid" ;
VAL_ 2332159641 CMD_of_Closed_Loop_09 0 "关闭" 1 "开启" ;
VAL_ 2332159641 SOCDiffHighFlg 0 "normal" 1 "alarm" ;
VAL_ 2332159642 M2P_Measure_Vol_10 65535 "Invalid" ;
VAL_ 2332159642 M2P_Current_10 65535 "Invalid" ;
VAL_ 2332159642 M2P_SOH_10 1023 "Invalid" ;
VAL_ 2332159642 M2P_RSOC_10 1023 "Invalid" ;
VAL_ 2332159642 M2P_DSOC_10 1023 "Invalid" ;
VAL_ 2332159642 CMD_of_Closed_Loop_10 0 "关闭" 1 "开启" ;
VAL_ 2332159642 SOCDiffHighFlg 0 "normal" 1 "alarm" ;
VAL_ 2332159643 M2P_Measure_Vol_11 65535 "Invalid" ;
VAL_ 2332159643 M2P_Current_11 65535 "Invalid" ;
VAL_ 2332159643 M2P_SOH_11 1023 "Invalid" ;
VAL_ 2332159643 M2P_RSOC_11 1023 "Invalid" ;
VAL_ 2332159643 M2P_DSOC_11 1023 "Invalid" ;
VAL_ 2332159643 CMD_of_Closed_Loop_11 0 "关闭" 1 "开启" ;
VAL_ 2332159643 SOCDiffHighFlg 0 "normal" 1 "alarm" ;
VAL_ 2332159644 M2P_Measure_Vol_12 65535 "Invalid" ;
VAL_ 2332159644 M2P_Current_12 65535 "Invalid" ;
VAL_ 2332159644 M2P_SOH_12 1023 "Invalid" ;
VAL_ 2332159644 M2P_RSOC_12 1023 "Invalid" ;
VAL_ 2332159644 M2P_DSOC_12 1023 "Invalid" ;
VAL_ 2332159644 CMD_of_Closed_Loop_12 0 "关闭" 1 "开启" ;
VAL_ 2332159644 SOCDiffHighFlg 0 "normal" 1 "alarm" ;
VAL_ 2332159645 M2P_Measure_Vol_13 65535 "Invalid" ;
VAL_ 2332159645 M2P_Current_13 65535 "Invalid" ;
VAL_ 2332159645 M2P_SOH_13 1023 "Invalid" ;
VAL_ 2332159645 M2P_RSOC_13 1023 "Invalid" ;
VAL_ 2332159645 M2P_DSOC_13 1023 "Invalid" ;
VAL_ 2332159645 CMD_of_Closed_Loop_13 0 "关闭" 1 "开启" ;
VAL_ 2332159645 SOCDiffHighFlg 0 "normal" 1 "alarm" ;
VAL_ 2332159646 M2P_Measure_Vol_14 65535 "Invalid" ;
VAL_ 2332159646 M2P_Current_14 65535 "Invalid" ;
VAL_ 2332159646 M2P_SOH_14 1023 "Invalid" ;
VAL_ 2332159646 M2P_RSOC_14 1023 "Invalid" ;
VAL_ 2332159646 M2P_DSOC_14 1023 "Invalid" ;
VAL_ 2332159646 CMD_of_Closed_Loop_14 0 "关闭" 1 "开启" ;
VAL_ 2332159646 SOCDiffHighFlg 0 "normal" 1 "alarm" ;
VAL_ 2332159647 M2P_Measure_Vol_15 65535 "Invalid" ;
VAL_ 2332159647 M2P_Current_15 65535 "Invalid" ;
VAL_ 2332159647 M2P_SOH_15 1023 "Invalid" ;
VAL_ 2332159647 M2P_RSOC_15 1023 "Invalid" ;
VAL_ 2332159647 M2P_DSOC_15 1023 "Invalid" ;
VAL_ 2332159647 CMD_of_Closed_Loop_15 0 "关闭" 1 "开启" ;
VAL_ 2332159647 SOCDiffHighFlg 0 "normal" 1 "alarm" ;
VAL_ 2332159648 M2P_Measure_Vol_16 65535 "Invalid" ;
VAL_ 2332159648 M2P_Current_16 65535 "Invalid" ;
VAL_ 2332159648 M2P_SOH_16 1023 "Invalid" ;
VAL_ 2332159648 M2P_RSOC_16 1023 "Invalid" ;
VAL_ 2332159648 M2P_DSOC_16 1023 "Invalid" ;
VAL_ 2332159648 CMD_of_Closed_Loop_16 0 "关闭" 1 "开启" ;
VAL_ 2332159648 SOCDiffHighFlg 0 "normal" 1 "alarm" ;
VAL_ 2332159649 M2P_Measure_Vol_17 65535 "Invalid" ;
VAL_ 2332159649 M2P_Current_17 65535 "Invalid" ;
VAL_ 2332159649 M2P_SOH_17 1023 "Invalid" ;
VAL_ 2332159649 M2P_RSOC_17 1023 "Invalid" ;
VAL_ 2332159649 M2P_DSOC_17 1023 "Invalid" ;
VAL_ 2332159649 CMD_of_Closed_Loop_17 0 "关闭" 1 "开启" ;
VAL_ 2332159649 SOCDiffHighFlg 0 "normal" 1 "alarm" ;
VAL_ 2332159650 M2P_Measure_Vol_18 65535 "Invalid" ;
VAL_ 2332159650 M2P_Current_18 65535 "Invalid" ;
VAL_ 2332159650 M2P_SOH_18 1023 "Invalid" ;
VAL_ 2332159650 M2P_RSOC_18 1023 "Invalid" ;
VAL_ 2332159650 M2P_DSOC_18 1023 "Invalid" ;
VAL_ 2332159650 CMD_of_Closed_Loop_18 0 "关闭" 1 "开启" ;
VAL_ 2332159650 SOCDiffHighFlg 0 "normal" 1 "alarm" ;
VAL_ 2332159651 M2P_Measure_Vol_19 65535 "Invalid" ;
VAL_ 2332159651 M2P_Current_19 65535 "Invalid" ;
VAL_ 2332159651 M2P_SOH_19 1023 "Invalid" ;
VAL_ 2332159651 M2P_RSOC_19 1023 "Invalid" ;
VAL_ 2332159651 M2P_DSOC_19 1023 "Invalid" ;
VAL_ 2332159651 CMD_of_Closed_Loop_19 0 "关闭" 1 "开启" ;
VAL_ 2332159651 SOCDiffHighFlg 0 "normal" 1 "alarm" ;
VAL_ 2332159652 M2P_Measure_Vol_20 65535 "Invalid" ;
VAL_ 2332159652 M2P_Current_20 65535 "Invalid" ;
VAL_ 2332159652 M2P_SOH_20 1023 "Invalid" ;
VAL_ 2332159652 M2P_RSOC_20 1023 "Invalid" ;
VAL_ 2332159652 M2P_DSOC_20 1023 "Invalid" ;
VAL_ 2332159652 CMD_of_Closed_Loop_20 0 "关闭" 1 "开启" ;
VAL_ 2332159652 SOCDiffHighFlg 0 "normal" 1 "alarm" ;
VAL_ 2332159653 M2P_Measure_Vol_21 65535 "Invalid" ;
VAL_ 2332159653 M2P_Current_21 65535 "Invalid" ;
VAL_ 2332159653 M2P_SOH_21 1023 "Invalid" ;
VAL_ 2332159653 M2P_RSOC_21 1023 "Invalid" ;
VAL_ 2332159653 M2P_DSOC_21 1023 "Invalid" ;
VAL_ 2332159653 CMD_of_Closed_Loop_21 0 "关闭" 1 "开启" ;
VAL_ 2332159653 SOCDiffHighFlg 0 "normal" 1 "alarm" ;
VAL_ 2332159654 M2P_Measure_Vol_22 65535 "Invalid" ;
VAL_ 2332159654 M2P_Current_22 65535 "Invalid" ;
VAL_ 2332159654 M2P_SOH_22 1023 "Invalid" ;
VAL_ 2332159654 M2P_RSOC_22 1023 "Invalid" ;
VAL_ 2332159654 M2P_DSOC_22 1023 "Invalid" ;
VAL_ 2332159654 CMD_of_Closed_Loop_22 0 "关闭" 1 "开启" ;
VAL_ 2332159654 SOCDiffHighFlg 0 "normal" 1 "alarm" ;
VAL_ 2332159655 M2P_Measure_Vol_23 65535 "Invalid" ;
VAL_ 2332159655 M2P_Current_23 65535 "Invalid" ;
VAL_ 2332159655 M2P_SOH_23 1023 "Invalid" ;
VAL_ 2332159655 M2P_RSOC_23 1023 "Invalid" ;
VAL_ 2332159655 M2P_DSOC_23 1023 "Invalid" ;
VAL_ 2332159655 CMD_of_Closed_Loop_23 0 "关闭" 1 "开启" ;
VAL_ 2332159655 SOCDiffHighFlg 0 "normal" 1 "alarm" ;
VAL_ 2332159656 M2P_Measure_Vol_24 65535 "Invalid" ;
VAL_ 2332159656 M2P_Current_24 65535 "Invalid" ;
VAL_ 2332159656 M2P_SOH_24 1023 "Invalid" ;
VAL_ 2332159656 M2P_RSOC_24 1023 "Invalid" ;
VAL_ 2332159656 M2P_DSOC_24 1023 "Invalid" ;
VAL_ 2332159656 CMD_of_Closed_Loop_24 0 "关闭" 1 "开启" ;
VAL_ 2332159656 SOCDiffHighFlg 0 "normal" 1 "alarm" ;
VAL_ 2332159657 M2P_Measure_Vol_25 65535 "Invalid" ;
VAL_ 2332159657 M2P_Current_25 65535 "Invalid" ;
VAL_ 2332159657 M2P_SOH_25 1023 "Invalid" ;
VAL_ 2332159657 M2P_RSOC_25 1023 "Invalid" ;
VAL_ 2332159657 M2P_DSOC_25 1023 "Invalid" ;
VAL_ 2332159657 CMD_of_Closed_Loop_25 0 "关闭" 1 "开启" ;
VAL_ 2332159657 SOCDiffHighFlg 0 "normal" 1 "alarm" ;
VAL_ 2332159658 M2P_Measure_Vol_26 65535 "Invalid" ;
VAL_ 2332159658 M2P_Current_26 65535 "Invalid" ;
VAL_ 2332159658 M2P_SOH_26 1023 "Invalid" ;
VAL_ 2332159658 M2P_RSOC_26 1023 "Invalid" ;
VAL_ 2332159658 M2P_DSOC_26 1023 "Invalid" ;
VAL_ 2332159658 CMD_of_Closed_Loop_26 0 "关闭" 1 "开启" ;
VAL_ 2332159658 SOCDiffHighFlg 0 "normal" 1 "alarm" ;
VAL_ 2332159659 M2P_Measure_Vol_27 65535 "Invalid" ;
VAL_ 2332159659 M2P_Current_27 65535 "Invalid" ;
VAL_ 2332159659 M2P_SOH_27 1023 "Invalid" ;
VAL_ 2332159659 M2P_RSOC_27 1023 "Invalid" ;
VAL_ 2332159659 M2P_DSOC_27 1023 "Invalid" ;
VAL_ 2332159659 CMD_of_Closed_Loop_27 0 "关闭" 1 "开启" ;
VAL_ 2332159659 SOCDiffHighFlg 0 "normal" 1 "alarm" ;
VAL_ 2332159660 M2P_Measure_Vol_28 65535 "Invalid" ;
VAL_ 2332159660 M2P_Current_28 65535 "Invalid" ;
VAL_ 2332159660 M2P_SOH_28 1023 "Invalid" ;
VAL_ 2332159660 M2P_RSOC_28 1023 "Invalid" ;
VAL_ 2332159660 M2P_DSOC_28 1023 "Invalid" ;
VAL_ 2332159660 CMD_of_Closed_Loop_28 0 "关闭" 1 "开启" ;
VAL_ 2332159660 SOCDiffHighFlg 0 "normal" 1 "alarm" ;
VAL_ 2332159661 M2P_Measure_Vol_29 65535 "Invalid" ;
VAL_ 2332159661 M2P_Current_29 65535 "Invalid" ;
VAL_ 2332159661 M2P_SOH_29 1023 "Invalid" ;
VAL_ 2332159661 M2P_RSOC_29 1023 "Invalid" ;
VAL_ 2332159661 M2P_DSOC_29 1023 "Invalid" ;
VAL_ 2332159661 CMD_of_Closed_Loop_29 0 "关闭" 1 "开启" ;
VAL_ 2332159661 SOCDiffHighFlg 0 "normal" 1 "alarm" ;
VAL_ 2332159662 M2P_Measure_Vol_30 65535 "Invalid" ;
VAL_ 2332159662 M2P_Current_30 65535 "Invalid" ;
VAL_ 2332159662 M2P_SOH_30 1023 "Invalid" ;
VAL_ 2332159662 M2P_RSOC_30 1023 "Invalid" ;
VAL_ 2332159662 M2P_DSOC_30 1023 "Invalid" ;
VAL_ 2332159662 CMD_of_Closed_Loop_30 0 "关闭" 1 "开启" ;
VAL_ 2332159662 SOCDiffHighFlg 0 "normal" 1 "alarm" ;
VAL_ 2332159663 M2P_Measure_Vol_31 65535 "Invalid" ;
VAL_ 2332159663 M2P_Current_31 65535 "Invalid" ;
VAL_ 2332159663 M2P_SOH_31 1023 "Invalid" ;
VAL_ 2332159663 M2P_RSOC_31 1023 "Invalid" ;
VAL_ 2332159663 M2P_DSOC_31 1023 "Invalid" ;
VAL_ 2332159663 CMD_of_Closed_Loop_31 0 "关闭" 1 "开启" ;
VAL_ 2332159663 SOCDiffHighFlg 0 "normal" 1 "alarm" ;
VAL_ 2332225169 M2P_ST_Power_01 0 "系统未上高压" 1 "高压上电完成" ;
VAL_ 2332225169 M2P_ST_Master_slave_01 0 "非主从集装箱架构" 1 "主从集装箱架构" ;
VAL_ 2332225169 M2P_Status_Fan_SW_01 0 "Off" 1 "On" ;
VAL_ 2332225169 M2P_Circuit_Breaker_01 0 "Off" 1 "Breaker1 On" 2 "Breaker2 On" 4 "Breaker3 On" 8 "Breaker4 On" 16 "Breaker5 On" 32 "Breaker6 On" ;
VAL_ 2332225169 M2P_RackInhabitResult 0 "Invalid" 1 "Successful" 2 "Fail" ;
VAL_ 2332225169 M2P_STofSBMUAutoCoding_01 0 "Invalid" 1 "Successful" 2 "Failed" 3 "Invalid" ;
VAL_ 2332225169 M2P_LvSelfLock 0 "Disable" 1 "Enable" ;
VAL_ 2332225169 M2P_SbmuPwrOnFlg 0 "Off" 1 "On" ;
VAL_ 2332225169 M2P_InsulPwrOnFlg 0 "Off" 1 "On" ;
VAL_ 2332225169 M2P_HvOffReqFlg 0 "Disable" 1 "Enable" ;
VAL_ 2332225169 M2P_HvOnAllowFlg 0 "Not Allow" 1 "Allow" ;
VAL_ 2332225169 M2P_SBMULvoffAbnomal 0 "No" 1 "SBMULvoffAbnomal" ;
VAL_ 2332225169 M2P_LVPwrDFaultR 0 "Invalid" 1 "BusCurrOver" 2 "Mrelay online" ;
VAL_ 2332225169 M2P_SysRunState 0 "SYS_Initial_ST" 1 "SYS_Normal_ST" 2 "SYS_Full_ST" 3 "SYS_Empty_ST" 4 "SYS_Alarm_ST" 5 "SYS_Fault_ST" ;
VAL_ 2332225170 M2P_ST_Power_02 0 "系统未上高压" 1 "高压上电完成" ;
VAL_ 2332225170 M2P_ST_Master_slave_02 0 "非主从集装箱架构" 1 "主从集装箱架构" ;
VAL_ 2332225170 M2P_Status_Fan_SW_02 0 "Off" 1 "On" ;
VAL_ 2332225170 M2P_Circuit_Breaker_02 0 "Off" 1 "Breaker1 On" 2 "Breaker2 On" 4 "Breaker3 On" 8 "Breaker4 On" 16 "Breaker5 On" 32 "Breaker6 On" ;
VAL_ 2332225170 M2P_RackInhabitResult 0 "Invalid" 1 "Successful" 2 "Fail" ;
VAL_ 2332225170 M2P_STofSBMUAutoCoding_02 0 "Invalid" 1 "Successful" 2 "Failed" 3 "Invalid" ;
VAL_ 2332225170 M2P_LvSelfLock 0 "Disable" 1 "Enable" ;
VAL_ 2332225170 M2P_SbmuPwrOnFlg 0 "Off" 1 "On" ;
VAL_ 2332225170 M2P_InsulPwrOnFlg 0 "Off" 1 "On" ;
VAL_ 2332225170 M2P_HvOffReqFlg 0 "Disable" 1 "Enable" ;
VAL_ 2332225170 M2P_HvOnAllowFlg 0 "Not Allow" 1 "Allow" ;
VAL_ 2332225170 M2P_SBMULvoffAbnomal 0 "No" 1 "SBMULvoffAbnomal" ;
VAL_ 2332225170 M2P_LVPwrDFaultR 0 "Invalid" 1 "BusCurrOver" 2 "Mrelay online" ;
VAL_ 2332225170 M2P_SysRunState 0 "SYS_Initial_ST" 1 "SYS_Normal_ST" 2 "SYS_Full_ST" 3 "SYS_Empty_ST" 4 "SYS_Alarm_ST" 5 "SYS_Fault_ST" ;
VAL_ 2332225171 M2P_ST_Power_03 0 "系统未上高压" 1 "高压上电完成" ;
VAL_ 2332225171 M2P_ST_Master_slave_03 0 "非主从集装箱架构" 1 "主从集装箱架构" ;
VAL_ 2332225171 M2P_Status_Fan_SW_03 0 "Off" 1 "On" ;
VAL_ 2332225171 M2P_Circuit_Breaker_03 0 "Off" 1 "Breaker1 On" 2 "Breaker2 On" 4 "Breaker3 On" 8 "Breaker4 On" 16 "Breaker5 On" 32 "Breaker6 On" ;
VAL_ 2332225171 M2P_RackInhabitResult 0 "Invalid" 1 "Successful" 2 "Fail" ;
VAL_ 2332225171 M2P_STofSBMUAutoCoding_03 0 "Invalid" 1 "Successful" 2 "Failed" 3 "Invalid" ;
VAL_ 2332225171 M2P_LvSelfLock 0 "Disable" 1 "Enable" ;
VAL_ 2332225171 M2P_SbmuPwrOnFlg 0 "Off" 1 "On" ;
VAL_ 2332225171 M2P_InsulPwrOnFlg 0 "Off" 1 "On" ;
VAL_ 2332225171 M2P_HvOffReqFlg 0 "Disable" 1 "Enable" ;
VAL_ 2332225171 M2P_HvOnAllowFlg 0 "Not Allow" 1 "Allow" ;
VAL_ 2332225171 M2P_SBMULvoffAbnomal 0 "No" 1 "SBMULvoffAbnomal" ;
VAL_ 2332225171 M2P_LVPwrDFaultR 0 "Invalid" 1 "BusCurrOver" 2 "Mrelay online" ;
VAL_ 2332225171 M2P_SysRunState 0 "SYS_Initial_ST" 1 "SYS_Normal_ST" 2 "SYS_Full_ST" 3 "SYS_Empty_ST" 4 "SYS_Alarm_ST" 5 "SYS_Fault_ST" ;
VAL_ 2332225172 M2P_ST_Power_04 0 "系统未上高压" 1 "高压上电完成" ;
VAL_ 2332225172 M2P_ST_Master_slave_04 0 "非主从集装箱架构" 1 "主从集装箱架构" ;
VAL_ 2332225172 M2P_Status_Fan_SW_04 0 "Off" 1 "On" ;
VAL_ 2332225172 M2P_Circuit_Breaker_04 0 "Off" 1 "Breaker1 On" 2 "Breaker2 On" 4 "Breaker3 On" 8 "Breaker4 On" 16 "Breaker5 On" 32 "Breaker6 On" ;
VAL_ 2332225172 M2P_RackInhabitResult 0 "Invalid" 1 "Successful" 2 "Fail" ;
VAL_ 2332225172 M2P_STofSBMUAutoCoding_04 0 "Invalid" 1 "Successful" 2 "Failed" 3 "Invalid" ;
VAL_ 2332225172 M2P_LvSelfLock 0 "Disable" 1 "Enable" ;
VAL_ 2332225172 M2P_SbmuPwrOnFlg 0 "Off" 1 "On" ;
VAL_ 2332225172 M2P_InsulPwrOnFlg 0 "Off" 1 "On" ;
VAL_ 2332225172 M2P_HvOffReqFlg 0 "Disable" 1 "Enable" ;
VAL_ 2332225172 M2P_HvOnAllowFlg 0 "Not Allow" 1 "Allow" ;
VAL_ 2332225172 M2P_SBMULvoffAbnomal 0 "No" 1 "SBMULvoffAbnomal" ;
VAL_ 2332225172 M2P_LVPwrDFaultR 0 "Invalid" 1 "BusCurrOver" 2 "Mrelay online" ;
VAL_ 2332225172 M2P_SysRunState 0 "SYS_Initial_ST" 1 "SYS_Normal_ST" 2 "SYS_Full_ST" 3 "SYS_Empty_ST" 4 "SYS_Alarm_ST" 5 "SYS_Fault_ST" ;
VAL_ 2332225173 M2P_ST_Power_05 0 "系统未上高压" 1 "高压上电完成" ;
VAL_ 2332225173 M2P_ST_Master_slave_05 0 "非主从集装箱架构" 1 "主从集装箱架构" ;
VAL_ 2332225173 M2P_Status_Fan_SW_05 0 "Off" 1 "On" ;
VAL_ 2332225173 M2P_Circuit_Breaker_05 0 "Off" 1 "Breaker1 On" 2 "Breaker2 On" 4 "Breaker3 On" 8 "Breaker4 On" 16 "Breaker5 On" 32 "Breaker6 On" ;
VAL_ 2332225173 M2P_RackInhabitResult 0 "Invalid" 1 "Successful" 2 "Fail" ;
VAL_ 2332225173 M2P_STofSBMUAutoCoding_05 0 "Invalid" 1 "Successful" 2 "Failed" 3 "Invalid" ;
VAL_ 2332225173 M2P_LvSelfLock 0 "Disable" 1 "Enable" ;
VAL_ 2332225173 M2P_SbmuPwrOnFlg 0 "Off" 1 "On" ;
VAL_ 2332225173 M2P_InsulPwrOnFlg 0 "Off" 1 "On" ;
VAL_ 2332225173 M2P_HvOffReqFlg 0 "Disable" 1 "Enable" ;
VAL_ 2332225173 M2P_HvOnAllowFlg 0 "Not Allow" 1 "Allow" ;
VAL_ 2332225173 M2P_SBMULvoffAbnomal 0 "No" 1 "SBMULvoffAbnomal" ;
VAL_ 2332225173 M2P_LVPwrDFaultR 0 "Invalid" 1 "BusCurrOver" 2 "Mrelay online" ;
VAL_ 2332225173 M2P_SysRunState 0 "SYS_Initial_ST" 1 "SYS_Normal_ST" 2 "SYS_Full_ST" 3 "SYS_Empty_ST" 4 "SYS_Alarm_ST" 5 "SYS_Fault_ST" ;
VAL_ 2332225174 M2P_ST_Power_06 0 "系统未上高压" 1 "高压上电完成" ;
VAL_ 2332225174 M2P_ST_Master_slave_06 0 "非主从集装箱架构" 1 "主从集装箱架构" ;
VAL_ 2332225174 M2P_Status_Fan_SW_06 0 "Off" 1 "On" ;
VAL_ 2332225174 M2P_Circuit_Breaker_06 0 "Off" 1 "Breaker1 On" 2 "Breaker2 On" 4 "Breaker3 On" 8 "Breaker4 On" 16 "Breaker5 On" 32 "Breaker6 On" ;
VAL_ 2332225174 M2P_RackInhabitResult 0 "Invalid" 1 "Successful" 2 "Fail" ;
VAL_ 2332225174 M2P_STofSBMUAutoCoding_06 0 "Invalid" 1 "Successful" 2 "Failed" 3 "Invalid" ;
VAL_ 2332225174 M2P_LvSelfLock 0 "Disable" 1 "Enable" ;
VAL_ 2332225174 M2P_SbmuPwrOnFlg 0 "Off" 1 "On" ;
VAL_ 2332225174 M2P_InsulPwrOnFlg 0 "Off" 1 "On" ;
VAL_ 2332225174 M2P_HvOffReqFlg 0 "Disable" 1 "Enable" ;
VAL_ 2332225174 M2P_HvOnAllowFlg 0 "Not Allow" 1 "Allow" ;
VAL_ 2332225174 M2P_SBMULvoffAbnomal 0 "No" 1 "SBMULvoffAbnomal" ;
VAL_ 2332225174 M2P_LVPwrDFaultR 0 "Invalid" 1 "BusCurrOver" 2 "Mrelay online" ;
VAL_ 2332225174 M2P_SysRunState 0 "SYS_Initial_ST" 1 "SYS_Normal_ST" 2 "SYS_Full_ST" 3 "SYS_Empty_ST" 4 "SYS_Alarm_ST" 5 "SYS_Fault_ST" ;
VAL_ 2332225175 M2P_ST_Power_07 0 "系统未上高压" 1 "高压上电完成" ;
VAL_ 2332225175 M2P_ST_Master_slave_07 0 "非主从集装箱架构" 1 "主从集装箱架构" ;
VAL_ 2332225175 M2P_Status_Fan_SW_07 0 "Off" 1 "On" ;
VAL_ 2332225175 M2P_Circuit_Breaker_07 0 "Off" 1 "Breaker1 On" 2 "Breaker2 On" 4 "Breaker3 On" 8 "Breaker4 On" 16 "Breaker5 On" 32 "Breaker6 On" ;
VAL_ 2332225175 M2P_RackInhabitResult 0 "Invalid" 1 "Successful" 2 "Fail" ;
VAL_ 2332225175 M2P_STofSBMUAutoCoding_07 0 "Invalid" 1 "Successful" 2 "Failed" 3 "Invalid" ;
VAL_ 2332225175 M2P_LvSelfLock 0 "Disable" 1 "Enable" ;
VAL_ 2332225175 M2P_SbmuPwrOnFlg 0 "Off" 1 "On" ;
VAL_ 2332225175 M2P_InsulPwrOnFlg 0 "Off" 1 "On" ;
VAL_ 2332225175 M2P_HvOffReqFlg 0 "Disable" 1 "Enable" ;
VAL_ 2332225175 M2P_HvOnAllowFlg 0 "Not Allow" 1 "Allow" ;
VAL_ 2332225175 M2P_SBMULvoffAbnomal 0 "No" 1 "SBMULvoffAbnomal" ;
VAL_ 2332225175 M2P_LVPwrDFaultR 0 "Invalid" 1 "BusCurrOver" 2 "Mrelay online" ;
VAL_ 2332225175 M2P_SysRunState 0 "SYS_Initial_ST" 1 "SYS_Normal_ST" 2 "SYS_Full_ST" 3 "SYS_Empty_ST" 4 "SYS_Alarm_ST" 5 "SYS_Fault_ST" ;
VAL_ 2332225176 M2P_ST_Power_08 0 "系统未上高压" 1 "高压上电完成" ;
VAL_ 2332225176 M2P_ST_Master_slave_08 0 "非主从集装箱架构" 1 "主从集装箱架构" ;
VAL_ 2332225176 M2P_Status_Fan_SW_08 0 "Off" 1 "On" ;
VAL_ 2332225176 M2P_Circuit_Breaker_08 0 "Off" 1 "Breaker1 On" 2 "Breaker2 On" 4 "Breaker3 On" 8 "Breaker4 On" 16 "Breaker5 On" 32 "Breaker6 On" ;
VAL_ 2332225176 M2P_RackInhabitResult 0 "Invalid" 1 "Successful" 2 "Fail" ;
VAL_ 2332225176 M2P_STofSBMUAutoCoding_08 0 "Invalid" 1 "Successful" 2 "Failed" 3 "Invalid" ;
VAL_ 2332225176 M2P_LvSelfLock 0 "Disable" 1 "Enable" ;
VAL_ 2332225176 M2P_SbmuPwrOnFlg 0 "Off" 1 "On" ;
VAL_ 2332225176 M2P_InsulPwrOnFlg 0 "Off" 1 "On" ;
VAL_ 2332225176 M2P_HvOffReqFlg 0 "Disable" 1 "Enable" ;
VAL_ 2332225176 M2P_HvOnAllowFlg 0 "Not Allow" 1 "Allow" ;
VAL_ 2332225176 M2P_SBMULvoffAbnomal 0 "No" 1 "SBMULvoffAbnomal" ;
VAL_ 2332225176 M2P_LVPwrDFaultR 0 "Invalid" 1 "BusCurrOver" 2 "Mrelay online" ;
VAL_ 2332225176 M2P_SysRunState 0 "SYS_Initial_ST" 1 "SYS_Normal_ST" 2 "SYS_Full_ST" 3 "SYS_Empty_ST" 4 "SYS_Alarm_ST" 5 "SYS_Fault_ST" ;
VAL_ 2332225177 M2P_ST_Power_09 0 "系统未上高压" 1 "高压上电完成" ;
VAL_ 2332225177 M2P_ST_Master_slave_09 0 "非主从集装箱架构" 1 "主从集装箱架构" ;
VAL_ 2332225177 M2P_Status_Fan_SW_09 0 "Off" 1 "On" ;
VAL_ 2332225177 M2P_Circuit_Breaker_09 0 "Off" 1 "Breaker1 On" 2 "Breaker2 On" 4 "Breaker3 On" 8 "Breaker4 On" 16 "Breaker5 On" 32 "Breaker6 On" ;
VAL_ 2332225177 M2P_RackInhabitResult 0 "Invalid" 1 "Successful" 2 "Fail" ;
VAL_ 2332225177 M2P_STofSBMUAutoCoding_09 0 "Invalid" 1 "Successful" 2 "Failed" 3 "Invalid" ;
VAL_ 2332225177 M2P_LvSelfLock 0 "Disable" 1 "Enable" ;
VAL_ 2332225177 M2P_SbmuPwrOnFlg 0 "Off" 1 "On" ;
VAL_ 2332225177 M2P_InsulPwrOnFlg 0 "Off" 1 "On" ;
VAL_ 2332225177 M2P_HvOffReqFlg 0 "Disable" 1 "Enable" ;
VAL_ 2332225177 M2P_HvOnAllowFlg 0 "Not Allow" 1 "Allow" ;
VAL_ 2332225177 M2P_SBMULvoffAbnomal 0 "No" 1 "SBMULvoffAbnomal" ;
VAL_ 2332225177 M2P_LVPwrDFaultR 0 "Invalid" 1 "BusCurrOver" 2 "Mrelay online" ;
VAL_ 2332225177 M2P_SysRunState 0 "SYS_Initial_ST" 1 "SYS_Normal_ST" 2 "SYS_Full_ST" 3 "SYS_Empty_ST" 4 "SYS_Alarm_ST" 5 "SYS_Fault_ST" ;
VAL_ 2332225178 M2P_ST_Power_10 0 "系统未上高压" 1 "高压上电完成" ;
VAL_ 2332225178 M2P_ST_Master_slave_10 0 "非主从集装箱架构" 1 "主从集装箱架构" ;
VAL_ 2332225178 M2P_Status_Fan_SW_10 0 "Off" 1 "On" ;
VAL_ 2332225178 M2P_Circuit_Breaker_10 0 "Off" 1 "Breaker1 On" 2 "Breaker2 On" 4 "Breaker3 On" 8 "Breaker4 On" 16 "Breaker5 On" 32 "Breaker6 On" ;
VAL_ 2332225178 M2P_RackInhabitResult 0 "Invalid" 1 "Successful" 2 "Fail" ;
VAL_ 2332225178 M2P_STofSBMUAutoCoding_10 0 "Invalid" 1 "Successful" 2 "Failed" 3 "Invalid" ;
VAL_ 2332225178 M2P_LvSelfLock 0 "Disable" 1 "Enable" ;
VAL_ 2332225178 M2P_SbmuPwrOnFlg 0 "Off" 1 "On" ;
VAL_ 2332225178 M2P_InsulPwrOnFlg 0 "Off" 1 "On" ;
VAL_ 2332225178 M2P_HvOffReqFlg 0 "Disable" 1 "Enable" ;
VAL_ 2332225178 M2P_HvOnAllowFlg 0 "Not Allow" 1 "Allow" ;
VAL_ 2332225178 M2P_SBMULvoffAbnomal 0 "No" 1 "SBMULvoffAbnomal" ;
VAL_ 2332225178 M2P_LVPwrDFaultR 0 "Invalid" 1 "BusCurrOver" 2 "Mrelay online" ;
VAL_ 2332225178 M2P_SysRunState 0 "SYS_Initial_ST" 1 "SYS_Normal_ST" 2 "SYS_Full_ST" 3 "SYS_Empty_ST" 4 "SYS_Alarm_ST" 5 "SYS_Fault_ST" ;
VAL_ 2332225179 M2P_ST_Power_11 0 "系统未上高压" 1 "高压上电完成" ;
VAL_ 2332225179 M2P_ST_Master_slave_11 0 "非主从集装箱架构" 1 "主从集装箱架构" ;
VAL_ 2332225179 M2P_Status_Fan_SW_11 0 "Off" 1 "On" ;
VAL_ 2332225179 M2P_Circuit_Breaker_11 0 "Off" 1 "Breaker1 On" 2 "Breaker2 On" 4 "Breaker3 On" 8 "Breaker4 On" 16 "Breaker5 On" 32 "Breaker6 On" ;
VAL_ 2332225179 M2P_RackInhabitResult 0 "Invalid" 1 "Successful" 2 "Fail" ;
VAL_ 2332225179 M2P_STofSBMUAutoCoding_11 0 "Invalid" 1 "Successful" 2 "Failed" 3 "Invalid" ;
VAL_ 2332225179 M2P_LvSelfLock 0 "Disable" 1 "Enable" ;
VAL_ 2332225179 M2P_SbmuPwrOnFlg 0 "Off" 1 "On" ;
VAL_ 2332225179 M2P_InsulPwrOnFlg 0 "Off" 1 "On" ;
VAL_ 2332225179 M2P_HvOffReqFlg 0 "Disable" 1 "Enable" ;
VAL_ 2332225179 M2P_HvOnAllowFlg 0 "Not Allow" 1 "Allow" ;
VAL_ 2332225179 M2P_SBMULvoffAbnomal 0 "No" 1 "SBMULvoffAbnomal" ;
VAL_ 2332225179 M2P_LVPwrDFaultR 0 "Invalid" 1 "BusCurrOver" 2 "Mrelay online" ;
VAL_ 2332225179 M2P_SysRunState 0 "SYS_Initial_ST" 1 "SYS_Normal_ST" 2 "SYS_Full_ST" 3 "SYS_Empty_ST" 4 "SYS_Alarm_ST" 5 "SYS_Fault_ST" ;
VAL_ 2332225180 M2P_ST_Power_12 0 "系统未上高压" 1 "高压上电完成" ;
VAL_ 2332225180 M2P_ST_Master_slave_12 0 "非主从集装箱架构" 1 "主从集装箱架构" ;
VAL_ 2332225180 M2P_Status_Fan_SW_12 0 "Off" 1 "On" ;
VAL_ 2332225180 M2P_Circuit_Breaker_12 0 "Off" 1 "Breaker1 On" 2 "Breaker2 On" 4 "Breaker3 On" 8 "Breaker4 On" 16 "Breaker5 On" 32 "Breaker6 On" ;
VAL_ 2332225180 M2P_RackInhabitResult 0 "Invalid" 1 "Successful" 2 "Fail" ;
VAL_ 2332225180 M2P_STofSBMUAutoCoding_12 0 "Invalid" 1 "Successful" 2 "Failed" 3 "Invalid" ;
VAL_ 2332225180 M2P_LvSelfLock 0 "Disable" 1 "Enable" ;
VAL_ 2332225180 M2P_SbmuPwrOnFlg 0 "Off" 1 "On" ;
VAL_ 2332225180 M2P_InsulPwrOnFlg 0 "Off" 1 "On" ;
VAL_ 2332225180 M2P_HvOffReqFlg 0 "Disable" 1 "Enable" ;
VAL_ 2332225180 M2P_HvOnAllowFlg 0 "Not Allow" 1 "Allow" ;
VAL_ 2332225180 M2P_SBMULvoffAbnomal 0 "No" 1 "SBMULvoffAbnomal" ;
VAL_ 2332225180 M2P_LVPwrDFaultR 0 "Invalid" 1 "BusCurrOver" 2 "Mrelay online" ;
VAL_ 2332225180 M2P_SysRunState 0 "SYS_Initial_ST" 1 "SYS_Normal_ST" 2 "SYS_Full_ST" 3 "SYS_Empty_ST" 4 "SYS_Alarm_ST" 5 "SYS_Fault_ST" ;
VAL_ 2332225181 M2P_ST_Power_13 0 "系统未上高压" 1 "高压上电完成" ;
VAL_ 2332225181 M2P_ST_Master_slave_13 0 "非主从集装箱架构" 1 "主从集装箱架构" ;
VAL_ 2332225181 M2P_Status_Fan_SW_13 0 "Off" 1 "On" ;
VAL_ 2332225181 M2P_Circuit_Breaker_13 0 "Off" 1 "Breaker1 On" 2 "Breaker2 On" 4 "Breaker3 On" 8 "Breaker4 On" 16 "Breaker5 On" 32 "Breaker6 On" ;
VAL_ 2332225181 M2P_RackInhabitResult 0 "Invalid" 1 "Successful" 2 "Fail" ;
VAL_ 2332225181 M2P_STofSBMUAutoCoding_13 0 "Invalid" 1 "Successful" 2 "Failed" 3 "Invalid" ;
VAL_ 2332225181 M2P_LvSelfLock 0 "Disable" 1 "Enable" ;
VAL_ 2332225181 M2P_SbmuPwrOnFlg 0 "Off" 1 "On" ;
VAL_ 2332225181 M2P_InsulPwrOnFlg 0 "Off" 1 "On" ;
VAL_ 2332225181 M2P_HvOffReqFlg 0 "Disable" 1 "Enable" ;
VAL_ 2332225181 M2P_HvOnAllowFlg 0 "Not Allow" 1 "Allow" ;
VAL_ 2332225181 M2P_SBMULvoffAbnomal 0 "No" 1 "SBMULvoffAbnomal" ;
VAL_ 2332225181 M2P_LVPwrDFaultR 0 "Invalid" 1 "BusCurrOver" 2 "Mrelay online" ;
VAL_ 2332225181 M2P_SysRunState 0 "SYS_Initial_ST" 1 "SYS_Normal_ST" 2 "SYS_Full_ST" 3 "SYS_Empty_ST" 4 "SYS_Alarm_ST" 5 "SYS_Fault_ST" ;
VAL_ 2332225182 M2P_ST_Power_14 0 "系统未上高压" 1 "高压上电完成" ;
VAL_ 2332225182 M2P_ST_Master_slave_14 0 "非主从集装箱架构" 1 "主从集装箱架构" ;
VAL_ 2332225182 M2P_Status_Fan_SW_14 0 "Off" 1 "On" ;
VAL_ 2332225182 M2P_Circuit_Breaker_14 0 "Off" 1 "Breaker1 On" 2 "Breaker2 On" 4 "Breaker3 On" 8 "Breaker4 On" 16 "Breaker5 On" 32 "Breaker6 On" ;
VAL_ 2332225182 M2P_RackInhabitResult 0 "Invalid" 1 "Successful" 2 "Fail" ;
VAL_ 2332225182 M2P_STofSBMUAutoCoding_14 0 "Invalid" 1 "Successful" 2 "Failed" 3 "Invalid" ;
VAL_ 2332225182 M2P_LvSelfLock 0 "Disable" 1 "Enable" ;
VAL_ 2332225182 M2P_SbmuPwrOnFlg 0 "Off" 1 "On" ;
VAL_ 2332225182 M2P_InsulPwrOnFlg 0 "Off" 1 "On" ;
VAL_ 2332225182 M2P_HvOffReqFlg 0 "Disable" 1 "Enable" ;
VAL_ 2332225182 M2P_HvOnAllowFlg 0 "Not Allow" 1 "Allow" ;
VAL_ 2332225182 M2P_SBMULvoffAbnomal 0 "No" 1 "SBMULvoffAbnomal" ;
VAL_ 2332225182 M2P_LVPwrDFaultR 0 "Invalid" 1 "BusCurrOver" 2 "Mrelay online" ;
VAL_ 2332225182 M2P_SysRunState 0 "SYS_Initial_ST" 1 "SYS_Normal_ST" 2 "SYS_Full_ST" 3 "SYS_Empty_ST" 4 "SYS_Alarm_ST" 5 "SYS_Fault_ST" ;
VAL_ 2332225183 M2P_ST_Power_15 0 "系统未上高压" 1 "高压上电完成" ;
VAL_ 2332225183 M2P_ST_Master_slave_15 0 "非主从集装箱架构" 1 "主从集装箱架构" ;
VAL_ 2332225183 M2P_Status_Fan_SW_15 0 "Off" 1 "On" ;
VAL_ 2332225183 M2P_Circuit_Breaker_15 0 "Off" 1 "Breaker1 On" 2 "Breaker2 On" 4 "Breaker3 On" 8 "Breaker4 On" 16 "Breaker5 On" 32 "Breaker6 On" ;
VAL_ 2332225183 M2P_RackInhabitResult 0 "Invalid" 1 "Successful" 2 "Fail" ;
VAL_ 2332225183 M2P_STofSBMUAutoCoding_15 0 "Invalid" 1 "Successful" 2 "Failed" 3 "Invalid" ;
VAL_ 2332225183 M2P_LvSelfLock 0 "Disable" 1 "Enable" ;
VAL_ 2332225183 M2P_SbmuPwrOnFlg 0 "Off" 1 "On" ;
VAL_ 2332225183 M2P_InsulPwrOnFlg 0 "Off" 1 "On" ;
VAL_ 2332225183 M2P_HvOffReqFlg 0 "Disable" 1 "Enable" ;
VAL_ 2332225183 M2P_HvOnAllowFlg 0 "Not Allow" 1 "Allow" ;
VAL_ 2332225183 M2P_SBMULvoffAbnomal 0 "No" 1 "SBMULvoffAbnomal" ;
VAL_ 2332225183 M2P_LVPwrDFaultR 0 "Invalid" 1 "BusCurrOver" 2 "Mrelay online" ;
VAL_ 2332225183 M2P_SysRunState 0 "SYS_Initial_ST" 1 "SYS_Normal_ST" 2 "SYS_Full_ST" 3 "SYS_Empty_ST" 4 "SYS_Alarm_ST" 5 "SYS_Fault_ST" ;
VAL_ 2332225184 M2P_ST_Power_16 0 "系统未上高压" 1 "高压上电完成" ;
VAL_ 2332225184 M2P_ST_Master_slave_16 0 "非主从集装箱架构" 1 "主从集装箱架构" ;
VAL_ 2332225184 M2P_Status_Fan_SW_16 0 "Off" 1 "On" ;
VAL_ 2332225184 M2P_Circuit_Breaker_16 0 "Off" 1 "Breaker1 On" 2 "Breaker2 On" 4 "Breaker3 On" 8 "Breaker4 On" 16 "Breaker5 On" 32 "Breaker6 On" ;
VAL_ 2332225184 M2P_RackInhabitResult 0 "Invalid" 1 "Successful" 2 "Fail" ;
VAL_ 2332225184 M2P_STofSBMUAutoCoding_16 0 "Invalid" 1 "Successful" 2 "Failed" 3 "Invalid" ;
VAL_ 2332225184 M2P_LvSelfLock 0 "Disable" 1 "Enable" ;
VAL_ 2332225184 M2P_SbmuPwrOnFlg 0 "Off" 1 "On" ;
VAL_ 2332225184 M2P_InsulPwrOnFlg 0 "Off" 1 "On" ;
VAL_ 2332225184 M2P_HvOffReqFlg 0 "Disable" 1 "Enable" ;
VAL_ 2332225184 M2P_HvOnAllowFlg 0 "Not Allow" 1 "Allow" ;
VAL_ 2332225184 M2P_SBMULvoffAbnomal 0 "No" 1 "SBMULvoffAbnomal" ;
VAL_ 2332225184 M2P_LVPwrDFaultR 0 "Invalid" 1 "BusCurrOver" 2 "Mrelay online" ;
VAL_ 2332225184 M2P_SysRunState 0 "SYS_Initial_ST" 1 "SYS_Normal_ST" 2 "SYS_Full_ST" 3 "SYS_Empty_ST" 4 "SYS_Alarm_ST" 5 "SYS_Fault_ST" ;
VAL_ 2332225185 M2P_ST_Power_17 0 "系统未上高压" 1 "高压上电完成" ;
VAL_ 2332225185 M2P_ST_Master_slave_17 0 "非主从集装箱架构" 1 "主从集装箱架构" ;
VAL_ 2332225185 M2P_Status_Fan_SW_17 0 "Off" 1 "On" ;
VAL_ 2332225185 M2P_Circuit_Breaker_17 0 "Off" 1 "Breaker1 On" 2 "Breaker2 On" 4 "Breaker3 On" 8 "Breaker4 On" 16 "Breaker5 On" 32 "Breaker6 On" ;
VAL_ 2332225185 M2P_RackInhabitResult 0 "Invalid" 1 "Successful" 2 "Fail" ;
VAL_ 2332225185 M2P_STofSBMUAutoCoding_17 0 "Invalid" 1 "Successful" 2 "Failed" 3 "Invalid" ;
VAL_ 2332225185 M2P_LvSelfLock 0 "Disable" 1 "Enable" ;
VAL_ 2332225185 M2P_SbmuPwrOnFlg 0 "Off" 1 "On" ;
VAL_ 2332225185 M2P_InsulPwrOnFlg 0 "Off" 1 "On" ;
VAL_ 2332225185 M2P_HvOffReqFlg 0 "Disable" 1 "Enable" ;
VAL_ 2332225185 M2P_HvOnAllowFlg 0 "Not Allow" 1 "Allow" ;
VAL_ 2332225185 M2P_SBMULvoffAbnomal 0 "No" 1 "SBMULvoffAbnomal" ;
VAL_ 2332225185 M2P_LVPwrDFaultR 0 "Invalid" 1 "BusCurrOver" 2 "Mrelay online" ;
VAL_ 2332225185 M2P_SysRunState 0 "SYS_Initial_ST" 1 "SYS_Normal_ST" 2 "SYS_Full_ST" 3 "SYS_Empty_ST" 4 "SYS_Alarm_ST" 5 "SYS_Fault_ST" ;
VAL_ 2332225186 M2P_ST_Power_18 0 "系统未上高压" 1 "高压上电完成" ;
VAL_ 2332225186 M2P_ST_Master_slave_18 0 "非主从集装箱架构" 1 "主从集装箱架构" ;
VAL_ 2332225186 M2P_Status_Fan_SW_18 0 "Off" 1 "On" ;
VAL_ 2332225186 M2P_Circuit_Breaker_18 0 "Off" 1 "Breaker1 On" 2 "Breaker2 On" 4 "Breaker3 On" 8 "Breaker4 On" 16 "Breaker5 On" 32 "Breaker6 On" ;
VAL_ 2332225186 M2P_RackInhabitResult 0 "Invalid" 1 "Successful" 2 "Fail" ;
VAL_ 2332225186 M2P_STofSBMUAutoCoding_18 0 "Invalid" 1 "Successful" 2 "Failed" 3 "Invalid" ;
VAL_ 2332225186 M2P_LvSelfLock 0 "Disable" 1 "Enable" ;
VAL_ 2332225186 M2P_SbmuPwrOnFlg 0 "Off" 1 "On" ;
VAL_ 2332225186 M2P_InsulPwrOnFlg 0 "Off" 1 "On" ;
VAL_ 2332225186 M2P_HvOffReqFlg 0 "Disable" 1 "Enable" ;
VAL_ 2332225186 M2P_HvOnAllowFlg 0 "Not Allow" 1 "Allow" ;
VAL_ 2332225186 M2P_SBMULvoffAbnomal 0 "No" 1 "SBMULvoffAbnomal" ;
VAL_ 2332225186 M2P_LVPwrDFaultR 0 "Invalid" 1 "BusCurrOver" 2 "Mrelay online" ;
VAL_ 2332225186 M2P_SysRunState 0 "SYS_Initial_ST" 1 "SYS_Normal_ST" 2 "SYS_Full_ST" 3 "SYS_Empty_ST" 4 "SYS_Alarm_ST" 5 "SYS_Fault_ST" ;
VAL_ 2332225187 M2P_ST_Power_19 0 "系统未上高压" 1 "高压上电完成" ;
VAL_ 2332225187 M2P_ST_Master_slave_19 0 "非主从集装箱架构" 1 "主从集装箱架构" ;
VAL_ 2332225187 M2P_Status_Fan_SW_19 0 "Off" 1 "On" ;
VAL_ 2332225187 M2P_Circuit_Breaker_19 0 "Off" 1 "Breaker1 On" 2 "Breaker2 On" 4 "Breaker3 On" 8 "Breaker4 On" 16 "Breaker5 On" 32 "Breaker6 On" ;
VAL_ 2332225187 M2P_RackInhabitResult 0 "Invalid" 1 "Successful" 2 "Fail" ;
VAL_ 2332225187 M2P_STofSBMUAutoCoding_19 0 "Invalid" 1 "Successful" 2 "Failed" 3 "Invalid" ;
VAL_ 2332225187 M2P_LvSelfLock 0 "Disable" 1 "Enable" ;
VAL_ 2332225187 M2P_SbmuPwrOnFlg 0 "Off" 1 "On" ;
VAL_ 2332225187 M2P_InsulPwrOnFlg 0 "Off" 1 "On" ;
VAL_ 2332225187 M2P_HvOffReqFlg 0 "Disable" 1 "Enable" ;
VAL_ 2332225187 M2P_HvOnAllowFlg 0 "Not Allow" 1 "Allow" ;
VAL_ 2332225187 M2P_SBMULvoffAbnomal 0 "No" 1 "SBMULvoffAbnomal" ;
VAL_ 2332225187 M2P_LVPwrDFaultR 0 "Invalid" 1 "BusCurrOver" 2 "Mrelay online" ;
VAL_ 2332225187 M2P_SysRunState 0 "SYS_Initial_ST" 1 "SYS_Normal_ST" 2 "SYS_Full_ST" 3 "SYS_Empty_ST" 4 "SYS_Alarm_ST" 5 "SYS_Fault_ST" ;
VAL_ 2332225188 M2P_ST_Power_20 0 "系统未上高压" 1 "高压上电完成" ;
VAL_ 2332225188 M2P_ST_Master_slave_20 0 "非主从集装箱架构" 1 "主从集装箱架构" ;
VAL_ 2332225188 M2P_Status_Fan_SW_20 0 "Off" 1 "On" ;
VAL_ 2332225188 M2P_Circuit_Breaker_20 0 "Off" 1 "Breaker1 On" 2 "Breaker2 On" 4 "Breaker3 On" 8 "Breaker4 On" 16 "Breaker5 On" 32 "Breaker6 On" ;
VAL_ 2332225188 M2P_RackInhabitResult 0 "Invalid" 1 "Successful" 2 "Fail" ;
VAL_ 2332225188 M2P_STofSBMUAutoCoding_20 0 "Invalid" 1 "Successful" 2 "Failed" 3 "Invalid" ;
VAL_ 2332225188 M2P_LvSelfLock 0 "Disable" 1 "Enable" ;
VAL_ 2332225188 M2P_SbmuPwrOnFlg 0 "Off" 1 "On" ;
VAL_ 2332225188 M2P_InsulPwrOnFlg 0 "Off" 1 "On" ;
VAL_ 2332225188 M2P_HvOffReqFlg 0 "Disable" 1 "Enable" ;
VAL_ 2332225188 M2P_HvOnAllowFlg 0 "Not Allow" 1 "Allow" ;
VAL_ 2332225188 M2P_SBMULvoffAbnomal 0 "No" 1 "SBMULvoffAbnomal" ;
VAL_ 2332225188 M2P_LVPwrDFaultR 0 "Invalid" 1 "BusCurrOver" 2 "Mrelay online" ;
VAL_ 2332225188 M2P_SysRunState 0 "SYS_Initial_ST" 1 "SYS_Normal_ST" 2 "SYS_Full_ST" 3 "SYS_Empty_ST" 4 "SYS_Alarm_ST" 5 "SYS_Fault_ST" ;
VAL_ 2332225189 M2P_ST_Power_21 0 "系统未上高压" 1 "高压上电完成" ;
VAL_ 2332225189 M2P_ST_Master_slave_21 0 "非主从集装箱架构" 1 "主从集装箱架构" ;
VAL_ 2332225189 M2P_Status_Fan_SW_21 0 "Off" 1 "On" ;
VAL_ 2332225189 M2P_Circuit_Breaker_21 0 "Off" 1 "Breaker1 On" 2 "Breaker2 On" 4 "Breaker3 On" 8 "Breaker4 On" 16 "Breaker5 On" 32 "Breaker6 On" ;
VAL_ 2332225189 M2P_RackInhabitResult 0 "Invalid" 1 "Successful" 2 "Fail" ;
VAL_ 2332225189 M2P_STofSBMUAutoCoding_21 0 "Invalid" 1 "Successful" 2 "Failed" 3 "Invalid" ;
VAL_ 2332225189 M2P_LvSelfLock 0 "Disable" 1 "Enable" ;
VAL_ 2332225189 M2P_SbmuPwrOnFlg 0 "Off" 1 "On" ;
VAL_ 2332225189 M2P_InsulPwrOnFlg 0 "Off" 1 "On" ;
VAL_ 2332225189 M2P_HvOffReqFlg 0 "Disable" 1 "Enable" ;
VAL_ 2332225189 M2P_HvOnAllowFlg 0 "Not Allow" 1 "Allow" ;
VAL_ 2332225189 M2P_SBMULvoffAbnomal 0 "No" 1 "SBMULvoffAbnomal" ;
VAL_ 2332225189 M2P_LVPwrDFaultR 0 "Invalid" 1 "BusCurrOver" 2 "Mrelay online" ;
VAL_ 2332225189 M2P_SysRunState 0 "SYS_Initial_ST" 1 "SYS_Normal_ST" 2 "SYS_Full_ST" 3 "SYS_Empty_ST" 4 "SYS_Alarm_ST" 5 "SYS_Fault_ST" ;
VAL_ 2332225190 M2P_ST_Power_22 0 "系统未上高压" 1 "高压上电完成" ;
VAL_ 2332225190 M2P_ST_Master_slave_22 0 "非主从集装箱架构" 1 "主从集装箱架构" ;
VAL_ 2332225190 M2P_Status_Fan_SW_22 0 "Off" 1 "On" ;
VAL_ 2332225190 M2P_Circuit_Breaker_22 0 "Off" 1 "Breaker1 On" 2 "Breaker2 On" 4 "Breaker3 On" 8 "Breaker4 On" 16 "Breaker5 On" 32 "Breaker6 On" ;
VAL_ 2332225190 M2P_RackInhabitResult 0 "Invalid" 1 "Successful" 2 "Fail" ;
VAL_ 2332225190 M2P_STofSBMUAutoCoding_22 0 "Invalid" 1 "Successful" 2 "Failed" 3 "Invalid" ;
VAL_ 2332225190 M2P_LvSelfLock 0 "Disable" 1 "Enable" ;
VAL_ 2332225190 M2P_SbmuPwrOnFlg 0 "Off" 1 "On" ;
VAL_ 2332225190 M2P_InsulPwrOnFlg 0 "Off" 1 "On" ;
VAL_ 2332225190 M2P_HvOffReqFlg 0 "Disable" 1 "Enable" ;
VAL_ 2332225190 M2P_HvOnAllowFlg 0 "Not Allow" 1 "Allow" ;
VAL_ 2332225190 M2P_SBMULvoffAbnomal 0 "No" 1 "SBMULvoffAbnomal" ;
VAL_ 2332225190 M2P_LVPwrDFaultR 0 "Invalid" 1 "BusCurrOver" 2 "Mrelay online" ;
VAL_ 2332225190 M2P_SysRunState 0 "SYS_Initial_ST" 1 "SYS_Normal_ST" 2 "SYS_Full_ST" 3 "SYS_Empty_ST" 4 "SYS_Alarm_ST" 5 "SYS_Fault_ST" ;
VAL_ 2332225191 M2P_ST_Power_23 0 "系统未上高压" 1 "高压上电完成" ;
VAL_ 2332225191 M2P_ST_Master_slave_23 0 "非主从集装箱架构" 1 "主从集装箱架构" ;
VAL_ 2332225191 M2P_Status_Fan_SW_23 0 "Off" 1 "On" ;
VAL_ 2332225191 M2P_Circuit_Breaker_23 0 "Off" 1 "Breaker1 On" 2 "Breaker2 On" 4 "Breaker3 On" 8 "Breaker4 On" 16 "Breaker5 On" 32 "Breaker6 On" ;
VAL_ 2332225191 M2P_RackInhabitResult 0 "Invalid" 1 "Successful" 2 "Fail" ;
VAL_ 2332225191 M2P_STofSBMUAutoCoding_23 0 "Invalid" 1 "Successful" 2 "Failed" 3 "Invalid" ;
VAL_ 2332225191 M2P_LvSelfLock 0 "Disable" 1 "Enable" ;
VAL_ 2332225191 M2P_SbmuPwrOnFlg 0 "Off" 1 "On" ;
VAL_ 2332225191 M2P_InsulPwrOnFlg 0 "Off" 1 "On" ;
VAL_ 2332225191 M2P_HvOffReqFlg 0 "Disable" 1 "Enable" ;
VAL_ 2332225191 M2P_HvOnAllowFlg 0 "Not Allow" 1 "Allow" ;
VAL_ 2332225191 M2P_SBMULvoffAbnomal 0 "No" 1 "SBMULvoffAbnomal" ;
VAL_ 2332225191 M2P_LVPwrDFaultR 0 "Invalid" 1 "BusCurrOver" 2 "Mrelay online" ;
VAL_ 2332225191 M2P_SysRunState 0 "SYS_Initial_ST" 1 "SYS_Normal_ST" 2 "SYS_Full_ST" 3 "SYS_Empty_ST" 4 "SYS_Alarm_ST" 5 "SYS_Fault_ST" ;
VAL_ 2332225192 M2P_ST_Power_24 0 "系统未上高压" 1 "高压上电完成" ;
VAL_ 2332225192 M2P_ST_Master_slave_24 0 "非主从集装箱架构" 1 "主从集装箱架构" ;
VAL_ 2332225192 M2P_Status_Fan_SW_24 0 "Off" 1 "On" ;
VAL_ 2332225192 M2P_Circuit_Breaker_24 0 "Off" 1 "Breaker1 On" 2 "Breaker2 On" 4 "Breaker3 On" 8 "Breaker4 On" 16 "Breaker5 On" 32 "Breaker6 On" ;
VAL_ 2332225192 M2P_RackInhabitResult 0 "Invalid" 1 "Successful" 2 "Fail" ;
VAL_ 2332225192 M2P_STofSBMUAutoCoding_24 0 "Invalid" 1 "Successful" 2 "Failed" 3 "Invalid" ;
VAL_ 2332225192 M2P_LvSelfLock 0 "Disable" 1 "Enable" ;
VAL_ 2332225192 M2P_SbmuPwrOnFlg 0 "Off" 1 "On" ;
VAL_ 2332225192 M2P_InsulPwrOnFlg 0 "Off" 1 "On" ;
VAL_ 2332225192 M2P_HvOffReqFlg 0 "Disable" 1 "Enable" ;
VAL_ 2332225192 M2P_HvOnAllowFlg 0 "Not Allow" 1 "Allow" ;
VAL_ 2332225192 M2P_SBMULvoffAbnomal 0 "No" 1 "SBMULvoffAbnomal" ;
VAL_ 2332225192 M2P_LVPwrDFaultR 0 "Invalid" 1 "BusCurrOver" 2 "Mrelay online" ;
VAL_ 2332225192 M2P_SysRunState 0 "SYS_Initial_ST" 1 "SYS_Normal_ST" 2 "SYS_Full_ST" 3 "SYS_Empty_ST" 4 "SYS_Alarm_ST" 5 "SYS_Fault_ST" ;
VAL_ 2332225193 M2P_ST_Power_25 0 "系统未上高压" 1 "高压上电完成" ;
VAL_ 2332225193 M2P_ST_Master_slave_25 0 "非主从集装箱架构" 1 "主从集装箱架构" ;
VAL_ 2332225193 M2P_Status_Fan_SW_25 0 "Off" 1 "On" ;
VAL_ 2332225193 M2P_Circuit_Breaker_25 0 "Off" 1 "Breaker1 On" 2 "Breaker2 On" 4 "Breaker3 On" 8 "Breaker4 On" 16 "Breaker5 On" 32 "Breaker6 On" ;
VAL_ 2332225193 M2P_RackInhabitResult 0 "Invalid" 1 "Successful" 2 "Fail" ;
VAL_ 2332225193 M2P_STofSBMUAutoCoding_25 0 "Invalid" 1 "Successful" 2 "Failed" 3 "Invalid" ;
VAL_ 2332225193 M2P_LvSelfLock 0 "Disable" 1 "Enable" ;
VAL_ 2332225193 M2P_SbmuPwrOnFlg 0 "Off" 1 "On" ;
VAL_ 2332225193 M2P_InsulPwrOnFlg 0 "Off" 1 "On" ;
VAL_ 2332225193 M2P_HvOffReqFlg 0 "Disable" 1 "Enable" ;
VAL_ 2332225193 M2P_HvOnAllowFlg 0 "Not Allow" 1 "Allow" ;
VAL_ 2332225193 M2P_SBMULvoffAbnomal 0 "No" 1 "SBMULvoffAbnomal" ;
VAL_ 2332225193 M2P_LVPwrDFaultR 0 "Invalid" 1 "BusCurrOver" 2 "Mrelay online" ;
VAL_ 2332225193 M2P_SysRunState 0 "SYS_Initial_ST" 1 "SYS_Normal_ST" 2 "SYS_Full_ST" 3 "SYS_Empty_ST" 4 "SYS_Alarm_ST" 5 "SYS_Fault_ST" ;
VAL_ 2332225194 M2P_ST_Power_26 0 "系统未上高压" 1 "高压上电完成" ;
VAL_ 2332225194 M2P_ST_Master_slave_26 0 "非主从集装箱架构" 1 "主从集装箱架构" ;
VAL_ 2332225194 M2P_Status_Fan_SW_26 0 "Off" 1 "On" ;
VAL_ 2332225194 M2P_Circuit_Breaker_26 0 "Off" 1 "Breaker1 On" 2 "Breaker2 On" 4 "Breaker3 On" 8 "Breaker4 On" 16 "Breaker5 On" 32 "Breaker6 On" ;
VAL_ 2332225194 M2P_RackInhabitResult 0 "Invalid" 1 "Successful" 2 "Fail" ;
VAL_ 2332225194 M2P_STofSBMUAutoCoding_26 0 "Invalid" 1 "Successful" 2 "Failed" 3 "Invalid" ;
VAL_ 2332225194 M2P_LvSelfLock 0 "Disable" 1 "Enable" ;
VAL_ 2332225194 M2P_SbmuPwrOnFlg 0 "Off" 1 "On" ;
VAL_ 2332225194 M2P_InsulPwrOnFlg 0 "Off" 1 "On" ;
VAL_ 2332225194 M2P_HvOffReqFlg 0 "Disable" 1 "Enable" ;
VAL_ 2332225194 M2P_HvOnAllowFlg 0 "Not Allow" 1 "Allow" ;
VAL_ 2332225194 M2P_SBMULvoffAbnomal 0 "No" 1 "SBMULvoffAbnomal" ;
VAL_ 2332225194 M2P_LVPwrDFaultR 0 "Invalid" 1 "BusCurrOver" 2 "Mrelay online" ;
VAL_ 2332225194 M2P_SysRunState 0 "SYS_Initial_ST" 1 "SYS_Normal_ST" 2 "SYS_Full_ST" 3 "SYS_Empty_ST" 4 "SYS_Alarm_ST" 5 "SYS_Fault_ST" ;
VAL_ 2332225195 M2P_ST_Power_27 0 "系统未上高压" 1 "高压上电完成" ;
VAL_ 2332225195 M2P_ST_Master_slave_27 0 "非主从集装箱架构" 1 "主从集装箱架构" ;
VAL_ 2332225195 M2P_Status_Fan_SW_27 0 "Off" 1 "On" ;
VAL_ 2332225195 M2P_Circuit_Breaker_27 0 "Off" 1 "Breaker1 On" 2 "Breaker2 On" 4 "Breaker3 On" 8 "Breaker4 On" 16 "Breaker5 On" 32 "Breaker6 On" ;
VAL_ 2332225195 M2P_RackInhabitResult 0 "Invalid" 1 "Successful" 2 "Fail" ;
VAL_ 2332225195 M2P_STofSBMUAutoCoding_27 0 "Invalid" 1 "Successful" 2 "Failed" 3 "Invalid" ;
VAL_ 2332225195 M2P_LvSelfLock 0 "Disable" 1 "Enable" ;
VAL_ 2332225195 M2P_SbmuPwrOnFlg 0 "Off" 1 "On" ;
VAL_ 2332225195 M2P_InsulPwrOnFlg 0 "Off" 1 "On" ;
VAL_ 2332225195 M2P_HvOffReqFlg 0 "Disable" 1 "Enable" ;
VAL_ 2332225195 M2P_HvOnAllowFlg 0 "Not Allow" 1 "Allow" ;
VAL_ 2332225195 M2P_SBMULvoffAbnomal 0 "No" 1 "SBMULvoffAbnomal" ;
VAL_ 2332225195 M2P_LVPwrDFaultR 0 "Invalid" 1 "BusCurrOver" 2 "Mrelay online" ;
VAL_ 2332225195 M2P_SysRunState 0 "SYS_Initial_ST" 1 "SYS_Normal_ST" 2 "SYS_Full_ST" 3 "SYS_Empty_ST" 4 "SYS_Alarm_ST" 5 "SYS_Fault_ST" ;
VAL_ 2332225196 M2P_ST_Power_28 0 "系统未上高压" 1 "高压上电完成" ;
VAL_ 2332225196 M2P_ST_Master_slave_28 0 "非主从集装箱架构" 1 "主从集装箱架构" ;
VAL_ 2332225196 M2P_Status_Fan_SW_28 0 "Off" 1 "On" ;
VAL_ 2332225196 M2P_Circuit_Breaker_28 0 "Off" 1 "Breaker1 On" 2 "Breaker2 On" 4 "Breaker3 On" 8 "Breaker4 On" 16 "Breaker5 On" 32 "Breaker6 On" ;
VAL_ 2332225196 M2P_RackInhabitResult 0 "Invalid" 1 "Successful" 2 "Fail" ;
VAL_ 2332225196 M2P_STofSBMUAutoCoding_28 0 "Invalid" 1 "Successful" 2 "Failed" 3 "Invalid" ;
VAL_ 2332225196 M2P_LvSelfLock 0 "Disable" 1 "Enable" ;
VAL_ 2332225196 M2P_SbmuPwrOnFlg 0 "Off" 1 "On" ;
VAL_ 2332225196 M2P_InsulPwrOnFlg 0 "Off" 1 "On" ;
VAL_ 2332225196 M2P_HvOffReqFlg 0 "Disable" 1 "Enable" ;
VAL_ 2332225196 M2P_HvOnAllowFlg 0 "Not Allow" 1 "Allow" ;
VAL_ 2332225196 M2P_SBMULvoffAbnomal 0 "No" 1 "SBMULvoffAbnomal" ;
VAL_ 2332225196 M2P_LVPwrDFaultR 0 "Invalid" 1 "BusCurrOver" 2 "Mrelay online" ;
VAL_ 2332225196 M2P_SysRunState 0 "SYS_Initial_ST" 1 "SYS_Normal_ST" 2 "SYS_Full_ST" 3 "SYS_Empty_ST" 4 "SYS_Alarm_ST" 5 "SYS_Fault_ST" ;
VAL_ 2332225197 M2P_ST_Power_29 0 "系统未上高压" 1 "高压上电完成" ;
VAL_ 2332225197 M2P_ST_Master_slave_29 0 "非主从集装箱架构" 1 "主从集装箱架构" ;
VAL_ 2332225197 M2P_Status_Fan_SW_29 0 "Off" 1 "On" ;
VAL_ 2332225197 M2P_Circuit_Breaker_29 0 "Off" 1 "Breaker1 On" 2 "Breaker2 On" 4 "Breaker3 On" 8 "Breaker4 On" 16 "Breaker5 On" 32 "Breaker6 On" ;
VAL_ 2332225197 M2P_RackInhabitResult 0 "Invalid" 1 "Successful" 2 "Fail" ;
VAL_ 2332225197 M2P_STofSBMUAutoCoding_29 0 "Invalid" 1 "Successful" 2 "Failed" 3 "Invalid" ;
VAL_ 2332225197 M2P_LvSelfLock 0 "Disable" 1 "Enable" ;
VAL_ 2332225197 M2P_SbmuPwrOnFlg 0 "Off" 1 "On" ;
VAL_ 2332225197 M2P_InsulPwrOnFlg 0 "Off" 1 "On" ;
VAL_ 2332225197 M2P_HvOffReqFlg 0 "Disable" 1 "Enable" ;
VAL_ 2332225197 M2P_HvOnAllowFlg 0 "Not Allow" 1 "Allow" ;
VAL_ 2332225197 M2P_SBMULvoffAbnomal 0 "No" 1 "SBMULvoffAbnomal" ;
VAL_ 2332225197 M2P_LVPwrDFaultR 0 "Invalid" 1 "BusCurrOver" 2 "Mrelay online" ;
VAL_ 2332225197 M2P_SysRunState 0 "SYS_Initial_ST" 1 "SYS_Normal_ST" 2 "SYS_Full_ST" 3 "SYS_Empty_ST" 4 "SYS_Alarm_ST" 5 "SYS_Fault_ST" ;
VAL_ 2332225198 M2P_ST_Power_30 0 "系统未上高压" 1 "高压上电完成" ;
VAL_ 2332225198 M2P_ST_Master_slave_30 0 "非主从集装箱架构" 1 "主从集装箱架构" ;
VAL_ 2332225198 M2P_Status_Fan_SW_30 0 "Off" 1 "On" ;
VAL_ 2332225198 M2P_Circuit_Breaker_30 0 "Off" 1 "Breaker1 On" 2 "Breaker2 On" 4 "Breaker3 On" 8 "Breaker4 On" 16 "Breaker5 On" 32 "Breaker6 On" ;
VAL_ 2332225198 M2P_RackInhabitResult 0 "Invalid" 1 "Successful" 2 "Fail" ;
VAL_ 2332225198 M2P_STofSBMUAutoCoding_30 0 "Invalid" 1 "Successful" 2 "Failed" 3 "Invalid" ;
VAL_ 2332225198 M2P_LvSelfLock 0 "Disable" 1 "Enable" ;
VAL_ 2332225198 M2P_SbmuPwrOnFlg 0 "Off" 1 "On" ;
VAL_ 2332225198 M2P_InsulPwrOnFlg 0 "Off" 1 "On" ;
VAL_ 2332225198 M2P_HvOffReqFlg 0 "Disable" 1 "Enable" ;
VAL_ 2332225198 M2P_HvOnAllowFlg 0 "Not Allow" 1 "Allow" ;
VAL_ 2332225198 M2P_SBMULvoffAbnomal 0 "No" 1 "SBMULvoffAbnomal" ;
VAL_ 2332225198 M2P_LVPwrDFaultR 0 "Invalid" 1 "BusCurrOver" 2 "Mrelay online" ;
VAL_ 2332225198 M2P_SysRunState 0 "SYS_Initial_ST" 1 "SYS_Normal_ST" 2 "SYS_Full_ST" 3 "SYS_Empty_ST" 4 "SYS_Alarm_ST" 5 "SYS_Fault_ST" ;
VAL_ 2332225199 M2P_ST_Power_31 0 "系统未上高压" 1 "高压上电完成" ;
VAL_ 2332225199 M2P_ST_Master_slave_31 0 "非主从集装箱架构" 1 "主从集装箱架构" ;
VAL_ 2332225199 M2P_Status_Fan_SW_31 0 "Off" 1 "On" ;
VAL_ 2332225199 M2P_Circuit_Breaker_31 0 "Off" 1 "Breaker1 On" 2 "Breaker2 On" 4 "Breaker3 On" 8 "Breaker4 On" 16 "Breaker5 On" 32 "Breaker6 On" ;
VAL_ 2332225199 M2P_RackInhabitResult 0 "Invalid" 1 "Successful" 2 "Fail" ;
VAL_ 2332225199 M2P_STofSBMUAutoCoding_31 0 "Invalid" 1 "Successful" 2 "Failed" 3 "Invalid" ;
VAL_ 2332225199 M2P_LvSelfLock 0 "Disable" 1 "Enable" ;
VAL_ 2332225199 M2P_SbmuPwrOnFlg 0 "Off" 1 "On" ;
VAL_ 2332225199 M2P_InsulPwrOnFlg 0 "Off" 1 "On" ;
VAL_ 2332225199 M2P_HvOffReqFlg 0 "Disable" 1 "Enable" ;
VAL_ 2332225199 M2P_HvOnAllowFlg 0 "Not Allow" 1 "Allow" ;
VAL_ 2332225199 M2P_SBMULvoffAbnomal 0 "No" 1 "SBMULvoffAbnomal" ;
VAL_ 2332225199 M2P_LVPwrDFaultR 0 "Invalid" 1 "BusCurrOver" 2 "Mrelay online" ;
VAL_ 2332225199 M2P_SysRunState 0 "SYS_Initial_ST" 1 "SYS_Normal_ST" 2 "SYS_Full_ST" 3 "SYS_Empty_ST" 4 "SYS_Alarm_ST" 5 "SYS_Fault_ST" ;
VAL_ 2332290705 M2P_PermitMaxCharge_I_01 65535 "Invalid" ;
VAL_ 2332290705 M2P_PermitMaxDisCharge_I_01 65535 "Invalid" ;
VAL_ 2332290705 M2P_Evn_T1_01 204 "干接点使用/未作温度采样使用" 205 "无效" ;
VAL_ 2332290705 M2P_Evn_T2_01 204 "干接点使用/未作温度采样使用" 205 "无效" ;
VAL_ 2332290705 M2P_Evn_T3_01 204 "干接点使用/未作温度采样使用" 205 "无效" ;
VAL_ 2332290705 M2P_Evn_Humidity_01 255 "Invalid" ;
VAL_ 2332290706 M2P_PermitMaxCharge_I_02 65535 "Invalid" ;
VAL_ 2332290706 M2P_PermitMaxDisCharge_I_02 65535 "Invalid" ;
VAL_ 2332290706 M2P_Evn_T1_02 204 "干接点使用/未作温度采样使用" 205 "无效" ;
VAL_ 2332290706 M2P_Evn_T2_02 204 "干接点使用/未作温度采样使用" 205 "无效" ;
VAL_ 2332290706 M2P_Evn_T3_02 204 "干接点使用/未作温度采样使用" 205 "无效" ;
VAL_ 2332290706 M2P_Evn_Humidity_02 255 "Invalid" ;
VAL_ 2332290707 M2P_PermitMaxCharge_I_03 65535 "Invalid" ;
VAL_ 2332290707 M2P_PermitMaxDisCharge_I_03 65535 "Invalid" ;
VAL_ 2332290707 M2P_Evn_T1_03 204 "干接点使用/未作温度采样使用" 205 "无效" ;
VAL_ 2332290707 M2P_Evn_T2_03 204 "干接点使用/未作温度采样使用" 205 "无效" ;
VAL_ 2332290707 M2P_Evn_T3_03 204 "干接点使用/未作温度采样使用" 205 "无效" ;
VAL_ 2332290707 M2P_Evn_Humidity_03 255 "Invalid" ;
VAL_ 2332290708 M2P_PermitMaxCharge_I_04 65535 "Invalid" ;
VAL_ 2332290708 M2P_PermitMaxDisCharge_I_04 65535 "Invalid" ;
VAL_ 2332290708 M2P_Evn_T1_04 204 "干接点使用/未作温度采样使用" 205 "无效" ;
VAL_ 2332290708 M2P_Evn_T2_04 204 "干接点使用/未作温度采样使用" 205 "无效" ;
VAL_ 2332290708 M2P_Evn_T3_04 204 "干接点使用/未作温度采样使用" 205 "无效" ;
VAL_ 2332290708 M2P_Evn_Humidity_04 255 "Invalid" ;
VAL_ 2332290709 M2P_PermitMaxCharge_I_05 65535 "Invalid" ;
VAL_ 2332290709 M2P_PermitMaxDisCharge_I_05 65535 "Invalid" ;
VAL_ 2332290709 M2P_Evn_T1_05 204 "干接点使用/未作温度采样使用" 205 "无效" ;
VAL_ 2332290709 M2P_Evn_T2_05 204 "干接点使用/未作温度采样使用" 205 "无效" ;
VAL_ 2332290709 M2P_Evn_T3_05 204 "干接点使用/未作温度采样使用" 205 "无效" ;
VAL_ 2332290709 M2P_Evn_Humidity_05 255 "Invalid" ;
VAL_ 2332290710 M2P_PermitMaxCharge_I_06 65535 "Invalid" ;
VAL_ 2332290710 M2P_PermitMaxDisCharge_I_06 65535 "Invalid" ;
VAL_ 2332290710 M2P_Evn_T1_06 204 "干接点使用/未作温度采样使用" 205 "无效" ;
VAL_ 2332290710 M2P_Evn_T2_06 204 "干接点使用/未作温度采样使用" 205 "无效" ;
VAL_ 2332290710 M2P_Evn_T3_06 204 "干接点使用/未作温度采样使用" 205 "无效" ;
VAL_ 2332290710 M2P_Evn_Humidity_06 255 "Invalid" ;
VAL_ 2332290711 M2P_PermitMaxCharge_I_07 65535 "Invalid" ;
VAL_ 2332290711 M2P_PermitMaxDisCharge_I_07 65535 "Invalid" ;
VAL_ 2332290711 M2P_Evn_T1_07 204 "干接点使用/未作温度采样使用" 205 "无效" ;
VAL_ 2332290711 M2P_Evn_T2_07 204 "干接点使用/未作温度采样使用" 205 "无效" ;
VAL_ 2332290711 M2P_Evn_T3_07 204 "干接点使用/未作温度采样使用" 205 "无效" ;
VAL_ 2332290711 M2P_Evn_Humidity_07 255 "Invalid" ;
VAL_ 2332290712 M2P_PermitMaxCharge_I_08 65535 "Invalid" ;
VAL_ 2332290712 M2P_PermitMaxDisCharge_I_08 65535 "Invalid" ;
VAL_ 2332290712 M2P_Evn_T1_08 204 "干接点使用/未作温度采样使用" 205 "无效" ;
VAL_ 2332290712 M2P_Evn_T2_08 204 "干接点使用/未作温度采样使用" 205 "无效" ;
VAL_ 2332290712 M2P_Evn_T3_08 204 "干接点使用/未作温度采样使用" 205 "无效" ;
VAL_ 2332290712 M2P_Evn_Humidity_08 255 "Invalid" ;
VAL_ 2332290713 M2P_PermitMaxCharge_I_09 65535 "Invalid" ;
VAL_ 2332290713 M2P_PermitMaxDisCharge_I_09 65535 "Invalid" ;
VAL_ 2332290713 M2P_Evn_T1_09 204 "干接点使用/未作温度采样使用" 205 "无效" ;
VAL_ 2332290713 M2P_Evn_T2_09 204 "干接点使用/未作温度采样使用" 205 "无效" ;
VAL_ 2332290713 M2P_Evn_T3_09 204 "干接点使用/未作温度采样使用" 205 "无效" ;
VAL_ 2332290713 M2P_Evn_Humidity_09 255 "Invalid" ;
VAL_ 2332290714 M2P_PermitMaxCharge_I_10 65535 "Invalid" ;
VAL_ 2332290714 M2P_PermitMaxDisCharge_I_10 65535 "Invalid" ;
VAL_ 2332290714 M2P_Evn_T1_10 204 "干接点使用/未作温度采样使用" 205 "无效" ;
VAL_ 2332290714 M2P_Evn_T2_10 204 "干接点使用/未作温度采样使用" 205 "无效" ;
VAL_ 2332290714 M2P_Evn_T3_10 204 "干接点使用/未作温度采样使用" 205 "无效" ;
VAL_ 2332290714 M2P_Evn_Humidity_10 255 "Invalid" ;
VAL_ 2332290715 M2P_PermitMaxCharge_I_11 65535 "Invalid" ;
VAL_ 2332290715 M2P_PermitMaxDisCharge_I_11 65535 "Invalid" ;
VAL_ 2332290715 M2P_Evn_T1_11 204 "干接点使用/未作温度采样使用" 205 "无效" ;
VAL_ 2332290715 M2P_Evn_T2_11 204 "干接点使用/未作温度采样使用" 205 "无效" ;
VAL_ 2332290715 M2P_Evn_T3_11 204 "干接点使用/未作温度采样使用" 205 "无效" ;
VAL_ 2332290715 M2P_Evn_Humidity_11 255 "Invalid" ;
VAL_ 2332290716 M2P_PermitMaxCharge_I_12 65535 "Invalid" ;
VAL_ 2332290716 M2P_PermitMaxDisCharge_I_12 65535 "Invalid" ;
VAL_ 2332290716 M2P_Evn_T1_12 204 "干接点使用/未作温度采样使用" 205 "无效" ;
VAL_ 2332290716 M2P_Evn_T2_12 204 "干接点使用/未作温度采样使用" 205 "无效" ;
VAL_ 2332290716 M2P_Evn_T3_12 204 "干接点使用/未作温度采样使用" 205 "无效" ;
VAL_ 2332290716 M2P_Evn_Humidity_12 255 "Invalid" ;
VAL_ 2332290717 M2P_PermitMaxCharge_I_13 65535 "Invalid" ;
VAL_ 2332290717 M2P_PermitMaxDisCharge_I_13 65535 "Invalid" ;
VAL_ 2332290717 M2P_Evn_T1_13 204 "干接点使用/未作温度采样使用" 205 "无效" ;
VAL_ 2332290717 M2P_Evn_T2_13 204 "干接点使用/未作温度采样使用" 205 "无效" ;
VAL_ 2332290717 M2P_Evn_T3_13 204 "干接点使用/未作温度采样使用" 205 "无效" ;
VAL_ 2332290717 M2P_Evn_Humidity_13 255 "Invalid" ;
VAL_ 2332290718 M2P_PermitMaxCharge_I_14 65535 "Invalid" ;
VAL_ 2332290718 M2P_PermitMaxDisCharge_I_14 65535 "Invalid" ;
VAL_ 2332290718 M2P_Evn_T1_14 204 "干接点使用/未作温度采样使用" 205 "无效" ;
VAL_ 2332290718 M2P_Evn_T2_14 204 "干接点使用/未作温度采样使用" 205 "无效" ;
VAL_ 2332290718 M2P_Evn_T3_14 204 "干接点使用/未作温度采样使用" 205 "无效" ;
VAL_ 2332290718 M2P_Evn_Humidity_14 255 "Invalid" ;
VAL_ 2332290719 M2P_PermitMaxCharge_I_15 65535 "Invalid" ;
VAL_ 2332290719 M2P_PermitMaxDisCharge_I_15 65535 "Invalid" ;
VAL_ 2332290719 M2P_Evn_T1_15 204 "干接点使用/未作温度采样使用" 205 "无效" ;
VAL_ 2332290719 M2P_Evn_T2_15 204 "干接点使用/未作温度采样使用" 205 "无效" ;
VAL_ 2332290719 M2P_Evn_T3_15 204 "干接点使用/未作温度采样使用" 205 "无效" ;
VAL_ 2332290719 M2P_Evn_Humidity_15 255 "Invalid" ;
VAL_ 2332290720 M2P_PermitMaxCharge_I_16 65535 "Invalid" ;
VAL_ 2332290720 M2P_PermitMaxDisCharge_I_16 65535 "Invalid" ;
VAL_ 2332290720 M2P_Evn_T1_16 204 "干接点使用/未作温度采样使用" 205 "无效" ;
VAL_ 2332290720 M2P_Evn_T2_16 204 "干接点使用/未作温度采样使用" 205 "无效" ;
VAL_ 2332290720 M2P_Evn_T3_16 204 "干接点使用/未作温度采样使用" 205 "无效" ;
VAL_ 2332290720 M2P_Evn_Humidity_16 255 "Invalid" ;
VAL_ 2332290721 M2P_PermitMaxCharge_I_17 65535 "Invalid" ;
VAL_ 2332290721 M2P_PermitMaxDisCharge_I_17 65535 "Invalid" ;
VAL_ 2332290721 M2P_Evn_T1_17 204 "干接点使用/未作温度采样使用" 205 "无效" ;
VAL_ 2332290721 M2P_Evn_T2_17 204 "干接点使用/未作温度采样使用" 205 "无效" ;
VAL_ 2332290721 M2P_Evn_T3_17 204 "干接点使用/未作温度采样使用" 205 "无效" ;
VAL_ 2332290721 M2P_Evn_Humidity_17 255 "Invalid" ;
VAL_ 2332290722 M2P_PermitMaxCharge_I_18 65535 "Invalid" ;
VAL_ 2332290722 M2P_PermitMaxDisCharge_I_18 65535 "Invalid" ;
VAL_ 2332290722 M2P_Evn_T1_18 204 "干接点使用/未作温度采样使用" 205 "无效" ;
VAL_ 2332290722 M2P_Evn_T2_18 204 "干接点使用/未作温度采样使用" 205 "无效" ;
VAL_ 2332290722 M2P_Evn_T3_18 204 "干接点使用/未作温度采样使用" 205 "无效" ;
VAL_ 2332290722 M2P_Evn_Humidity_18 255 "Invalid" ;
VAL_ 2332290723 M2P_PermitMaxCharge_I_19 65535 "Invalid" ;
VAL_ 2332290723 M2P_PermitMaxDisCharge_I_19 65535 "Invalid" ;
VAL_ 2332290723 M2P_Evn_T1_19 204 "干接点使用/未作温度采样使用" 205 "无效" ;
VAL_ 2332290723 M2P_Evn_T2_19 204 "干接点使用/未作温度采样使用" 205 "无效" ;
VAL_ 2332290723 M2P_Evn_T3_19 204 "干接点使用/未作温度采样使用" 205 "无效" ;
VAL_ 2332290723 M2P_Evn_Humidity_19 255 "Invalid" ;
VAL_ 2332290724 M2P_PermitMaxCharge_I_20 65535 "Invalid" ;
VAL_ 2332290724 M2P_PermitMaxDisCharge_I_20 65535 "Invalid" ;
VAL_ 2332290724 M2P_Evn_T1_20 204 "干接点使用/未作温度采样使用" 205 "无效" ;
VAL_ 2332290724 M2P_Evn_T2_20 204 "干接点使用/未作温度采样使用" 205 "无效" ;
VAL_ 2332290724 M2P_Evn_T3_20 204 "干接点使用/未作温度采样使用" 205 "无效" ;
VAL_ 2332290724 M2P_Evn_Humidity_20 255 "Invalid" ;
VAL_ 2332290725 M2P_PermitMaxCharge_I_21 65535 "Invalid" ;
VAL_ 2332290725 M2P_PermitMaxDisCharge_I_21 65535 "Invalid" ;
VAL_ 2332290725 M2P_Evn_T1_21 204 "干接点使用/未作温度采样使用" 205 "无效" ;
VAL_ 2332290725 M2P_Evn_T2_21 204 "干接点使用/未作温度采样使用" 205 "无效" ;
VAL_ 2332290725 M2P_Evn_T3_21 204 "干接点使用/未作温度采样使用" 205 "无效" ;
VAL_ 2332290725 M2P_Evn_Humidity_21 255 "Invalid" ;
VAL_ 2332290726 M2P_PermitMaxCharge_I_22 65535 "Invalid" ;
VAL_ 2332290726 M2P_PermitMaxDisCharge_I_22 65535 "Invalid" ;
VAL_ 2332290726 M2P_Evn_T1_22 204 "干接点使用/未作温度采样使用" 205 "无效" ;
VAL_ 2332290726 M2P_Evn_T2_22 204 "干接点使用/未作温度采样使用" 205 "无效" ;
VAL_ 2332290726 M2P_Evn_T3_22 204 "干接点使用/未作温度采样使用" 205 "无效" ;
VAL_ 2332290726 M2P_Evn_Humidity_22 255 "Invalid" ;
VAL_ 2332290727 M2P_PermitMaxCharge_I_23 65535 "Invalid" ;
VAL_ 2332290727 M2P_PermitMaxDisCharge_I_23 65535 "Invalid" ;
VAL_ 2332290727 M2P_Evn_T1_23 204 "干接点使用/未作温度采样使用" 205 "无效" ;
VAL_ 2332290727 M2P_Evn_T2_23 204 "干接点使用/未作温度采样使用" 205 "无效" ;
VAL_ 2332290727 M2P_Evn_T3_23 204 "干接点使用/未作温度采样使用" 205 "无效" ;
VAL_ 2332290727 M2P_Evn_Humidity_23 255 "Invalid" ;
VAL_ 2332290728 M2P_PermitMaxCharge_I_24 65535 "Invalid" ;
VAL_ 2332290728 M2P_PermitMaxDisCharge_I_24 65535 "Invalid" ;
VAL_ 2332290728 M2P_Evn_T1_24 204 "干接点使用/未作温度采样使用" 205 "无效" ;
VAL_ 2332290728 M2P_Evn_T2_24 204 "干接点使用/未作温度采样使用" 205 "无效" ;
VAL_ 2332290728 M2P_Evn_T3_24 204 "干接点使用/未作温度采样使用" 205 "无效" ;
VAL_ 2332290728 M2P_Evn_Humidity_24 255 "Invalid" ;
VAL_ 2332290729 M2P_PermitMaxCharge_I_25 65535 "Invalid" ;
VAL_ 2332290729 M2P_PermitMaxDisCharge_I_25 65535 "Invalid" ;
VAL_ 2332290729 M2P_Evn_T1_25 204 "干接点使用/未作温度采样使用" 205 "无效" ;
VAL_ 2332290729 M2P_Evn_T2_25 204 "干接点使用/未作温度采样使用" 205 "无效" ;
VAL_ 2332290729 M2P_Evn_T3_25 204 "干接点使用/未作温度采样使用" 205 "无效" ;
VAL_ 2332290729 M2P_Evn_Humidity_25 255 "Invalid" ;
VAL_ 2332290730 M2P_PermitMaxCharge_I_26 65535 "Invalid" ;
VAL_ 2332290730 M2P_PermitMaxDisCharge_I_26 65535 "Invalid" ;
VAL_ 2332290730 M2P_Evn_T1_26 204 "干接点使用/未作温度采样使用" 205 "无效" ;
VAL_ 2332290730 M2P_Evn_T2_26 204 "干接点使用/未作温度采样使用" 205 "无效" ;
VAL_ 2332290730 M2P_Evn_T3_26 204 "干接点使用/未作温度采样使用" 205 "无效" ;
VAL_ 2332290730 M2P_Evn_Humidity_26 255 "Invalid" ;
VERSION ""

NS_ :

BS_:

BU_: MBMU PC SBMU IMM ETH DCDC LEMS

BO_ 2332290731 M2P_SUMDATA3__27: 8 MBMU
 SG_ M2P_PermitMaxCharge_I_27 : 0|16@1+ (1,-20000) [-20000|45535] "A"  PC
 SG_ M2P_PermitMaxDisCharge_I_27 : 16|16@1+ (1,-20000) [-20000|45535] "A"  PC
 SG_ M2P_Evn_T1_27 : 32|8@1+ (1,-50) [-50|205] "℃"  PC
 SG_ M2P_Evn_T2_27 : 40|8@1+ (1,-50) [-50|205] "℃"  PC
 SG_ M2P_Evn_T3_27 : 48|8@1+ (1,-50) [-50|205] "℃"  PC
 SG_ M2P_Evn_Humidity_27 : 56|8@1+ (1,0) [0|255] "%"  PC

BO_ 2332290732 M2P_SUMDATA3__28: 8 MBMU
 SG_ M2P_PermitMaxCharge_I_28 : 0|16@1+ (1,-20000) [-20000|45535] "A"  PC
 SG_ M2P_PermitMaxDisCharge_I_28 : 16|16@1+ (1,-20000) [-20000|45535] "A"  PC
 SG_ M2P_Evn_T1_28 : 32|8@1+ (1,-50) [-50|205] "℃"  PC
 SG_ M2P_Evn_T2_28 : 40|8@1+ (1,-50) [-50|205] "℃"  PC
 SG_ M2P_Evn_T3_28 : 48|8@1+ (1,-50) [-50|205] "℃"  PC
 SG_ M2P_Evn_Humidity_28 : 56|8@1+ (1,0) [0|255] "%"  PC

BO_ 2332290733 M2P_SUMDATA3__29: 8 MBMU
 SG_ M2P_PermitMaxCharge_I_29 : 0|16@1+ (1,-20000) [-20000|45535] "A"  PC
 SG_ M2P_PermitMaxDisCharge_I_29 : 16|16@1+ (1,-20000) [-20000|45535] "A"  PC
 SG_ M2P_Evn_T1_29 : 32|8@1+ (1,-50) [-50|205] "℃"  PC
 SG_ M2P_Evn_T2_29 : 40|8@1+ (1,-50) [-50|205] "℃"  PC
 SG_ M2P_Evn_T3_29 : 48|8@1+ (1,-50) [-50|205] "℃"  PC
 SG_ M2P_Evn_Humidity_29 : 56|8@1+ (1,0) [0|255] "%"  PC

BO_ 2332290734 M2P_SUMDATA3__30: 8 MBMU
 SG_ M2P_PermitMaxCharge_I_30 : 0|16@1+ (1,-20000) [-20000|45535] "A"  PC
 SG_ M2P_PermitMaxDisCharge_I_30 : 16|16@1+ (1,-20000) [-20000|45535] "A"  PC
 SG_ M2P_Evn_T1_30 : 32|8@1+ (1,-50) [-50|205] "℃"  PC
 SG_ M2P_Evn_T2_30 : 40|8@1+ (1,-50) [-50|205] "℃"  PC
 SG_ M2P_Evn_T3_30 : 48|8@1+ (1,-50) [-50|205] "℃"  PC
 SG_ M2P_Evn_Humidity_30 : 56|8@1+ (1,0) [0|255] "%"  PC

BO_ 2332290735 M2P_SUMDATA3__31: 8 MBMU
 SG_ M2P_PermitMaxCharge_I_31 : 0|16@1+ (1,-20000) [-20000|45535] "A"  PC
 SG_ M2P_PermitMaxDisCharge_I_31 : 16|16@1+ (1,-20000) [-20000|45535] "A"  PC
 SG_ M2P_Evn_T1_31 : 32|8@1+ (1,-50) [-50|205] "℃"  PC
 SG_ M2P_Evn_T2_31 : 40|8@1+ (1,-50) [-50|205] "℃"  PC
 SG_ M2P_Evn_T3_31 : 48|8@1+ (1,-50) [-50|205] "℃"  PC
 SG_ M2P_Evn_Humidity_31 : 56|8@1+ (1,0) [0|255] "%"  PC

BO_ 2332356241 M2P_SUMDATA4__01: 8 MBMU
 SG_ M2P_SysMaxVolt_01 : 0|16@1+ (1,0) [0|65535] "mV"  PC
 SG_ M2P_SysMinVolt_01 : 16|16@1+ (1,0) [0|65535] "mV"  PC
 SG_ M2P_SysAvgVolt_01 : 32|16@1+ (1,0) [0|65535] "mV"  PC
 SG_ M2P_Evn_T4_01 : 48|8@1+ (1,-50) [-50|205] "℃"  PC
 SG_ M2P_Bat_CorrectState_Require_01 : 56|8@1+ (1,0) [0|255] ""  PC

BO_ 2332356242 M2P_SUMDATA4__02: 8 MBMU
 SG_ M2P_SysMaxVolt_02 : 0|16@1+ (1,0) [0|65535] "mV"  PC
 SG_ M2P_SysMinVolt_02 : 16|16@1+ (1,0) [0|65535] "mV"  PC
 SG_ M2P_SysAvgVolt_02 : 32|16@1+ (1,0) [0|65535] "mV"  PC
 SG_ M2P_Evn_T4_02 : 48|8@1+ (1,-50) [-50|205] "℃"  PC
 SG_ M2P_Bat_CorrectState_Require_02 : 56|8@1+ (1,0) [0|255] ""  PC

BO_ 2332356243 M2P_SUMDATA4__03: 8 MBMU
 SG_ M2P_SysMaxVolt_03 : 0|16@1+ (1,0) [0|65535] "mV"  PC
 SG_ M2P_SysMinVolt_03 : 16|16@1+ (1,0) [0|65535] "mV"  PC
 SG_ M2P_SysAvgVolt_03 : 32|16@1+ (1,0) [0|65535] "mV"  PC
 SG_ M2P_Evn_T4_03 : 48|8@1+ (1,-50) [-50|205] "℃"  PC
 SG_ M2P_Bat_CorrectState_Require_03 : 56|8@1+ (1,0) [0|255] ""  PC

BO_ 2332356244 M2P_SUMDATA4__04: 8 MBMU
 SG_ M2P_SysMaxVolt_04 : 0|16@1+ (1,0) [0|65535] "mV"  PC
 SG_ M2P_SysMinVolt_04 : 16|16@1+ (1,0) [0|65535] "mV"  PC
 SG_ M2P_SysAvgVolt_04 : 32|16@1+ (1,0) [0|65535] "mV"  PC
 SG_ M2P_Evn_T4_04 : 48|8@1+ (1,-50) [-50|205] "℃"  PC
 SG_ M2P_Bat_CorrectState_Require_04 : 56|8@1+ (1,0) [0|255] ""  PC

BO_ 2332356245 M2P_SUMDATA4__05: 8 MBMU
 SG_ M2P_SysMaxVolt_05 : 0|16@1+ (1,0) [0|65535] "mV"  PC
 SG_ M2P_SysMinVolt_05 : 16|16@1+ (1,0) [0|65535] "mV"  PC
 SG_ M2P_SysAvgVolt_05 : 32|16@1+ (1,0) [0|65535] "mV"  PC
 SG_ M2P_Evn_T4_05 : 48|8@1+ (1,-50) [-50|205] "℃"  PC
 SG_ M2P_Bat_CorrectState_Require_05 : 56|8@1+ (1,0) [0|255] ""  PC

BO_ 2332356246 M2P_SUMDATA4__06: 8 MBMU
 SG_ M2P_SysMaxVolt_06 : 0|16@1+ (1,0) [0|65535] "mV"  PC
 SG_ M2P_SysMinVolt_06 : 16|16@1+ (1,0) [0|65535] "mV"  PC
 SG_ M2P_SysAvgVolt_06 : 32|16@1+ (1,0) [0|65535] "mV"  PC
 SG_ M2P_Evn_T4_06 : 48|8@1+ (1,-50) [-50|205] "℃"  PC
 SG_ M2P_Bat_CorrectState_Require_06 : 56|8@1+ (1,0) [0|255] ""  PC

BO_ 2332356247 M2P_SUMDATA4__07: 8 MBMU
 SG_ M2P_SysMaxVolt_07 : 0|16@1+ (1,0) [0|65535] "mV"  PC
 SG_ M2P_SysMinVolt_07 : 16|16@1+ (1,0) [0|65535] "mV"  PC
 SG_ M2P_SysAvgVolt_07 : 32|16@1+ (1,0) [0|65535] "mV"  PC
 SG_ M2P_Evn_T4_07 : 48|8@1+ (1,-50) [-50|205] "℃"  PC
 SG_ M2P_Bat_CorrectState_Require_07 : 56|8@1+ (1,0) [0|255] ""  PC

BO_ 2332356248 M2P_SUMDATA4__08: 8 MBMU
 SG_ M2P_SysMaxVolt_08 : 0|16@1+ (1,0) [0|65535] "mV"  PC
 SG_ M2P_SysMinVolt_08 : 16|16@1+ (1,0) [0|65535] "mV"  PC
 SG_ M2P_SysAvgVolt_08 : 32|16@1+ (1,0) [0|65535] "mV"  PC
 SG_ M2P_Evn_T4_08 : 48|8@1+ (1,-50) [-50|205] "℃"  PC
 SG_ M2P_Bat_CorrectState_Require_08 : 56|8@1+ (1,0) [0|255] ""  PC

BO_ 2332356249 M2P_SUMDATA4__09: 8 MBMU
 SG_ M2P_SysMaxVolt_09 : 0|16@1+ (1,0) [0|65535] "mV"  PC
 SG_ M2P_SysMinVolt_09 : 16|16@1+ (1,0) [0|65535] "mV"  PC
 SG_ M2P_SysAvgVolt_09 : 32|16@1+ (1,0) [0|65535] "mV"  PC
 SG_ M2P_Evn_T4_09 : 48|8@1+ (1,-50) [-50|205] "℃"  PC
 SG_ M2P_Bat_CorrectState_Require_09 : 56|8@1+ (1,0) [0|255] ""  PC

BO_ 2332356250 M2P_SUMDATA4__10: 8 MBMU
 SG_ M2P_SysMaxVolt_10 : 0|16@1+ (1,0) [0|65535] "mV"  PC
 SG_ M2P_SysMinVolt_10 : 16|16@1+ (1,0) [0|65535] "mV"  PC
 SG_ M2P_SysAvgVolt_10 : 32|16@1+ (1,0) [0|65535] "mV"  PC
 SG_ M2P_Evn_T4_10 : 48|8@1+ (1,-50) [-50|205] "℃"  PC
 SG_ M2P_Bat_CorrectState_Require_10 : 56|8@1+ (1,0) [0|255] ""  PC

BO_ 2332356251 M2P_SUMDATA4__11: 8 MBMU
 SG_ M2P_SysMaxVolt_11 : 0|16@1+ (1,0) [0|65535] "mV"  PC
 SG_ M2P_SysMinVolt_11 : 16|16@1+ (1,0) [0|65535] "mV"  PC
 SG_ M2P_SysAvgVolt_11 : 32|16@1+ (1,0) [0|65535] "mV"  PC
 SG_ M2P_Evn_T4_11 : 48|8@1+ (1,-50) [-50|205] "℃"  PC
 SG_ M2P_Bat_CorrectState_Require_11 : 56|8@1+ (1,0) [0|255] ""  PC

BO_ 2332356252 M2P_SUMDATA4__12: 8 MBMU
 SG_ M2P_SysMaxVolt_12 : 0|16@1+ (1,0) [0|65535] "mV"  PC
 SG_ M2P_SysMinVolt_12 : 16|16@1+ (1,0) [0|65535] "mV"  PC
 SG_ M2P_SysAvgVolt_12 : 32|16@1+ (1,0) [0|65535] "mV"  PC
 SG_ M2P_Evn_T4_12 : 48|8@1+ (1,-50) [-50|205] "℃"  PC
 SG_ M2P_Bat_CorrectState_Require_12 : 56|8@1+ (1,0) [0|255] ""  PC

BO_ 2332356253 M2P_SUMDATA4__13: 8 MBMU
 SG_ M2P_SysMaxVolt_13 : 0|16@1+ (1,0) [0|65535] "mV"  PC
 SG_ M2P_SysMinVolt_13 : 16|16@1+ (1,0) [0|65535] "mV"  PC
 SG_ M2P_SysAvgVolt_13 : 32|16@1+ (1,0) [0|65535] "mV"  PC
 SG_ M2P_Evn_T4_13 : 48|8@1+ (1,-50) [-50|205] "℃"  PC
 SG_ M2P_Bat_CorrectState_Require_13 : 56|8@1+ (1,0) [0|255] ""  PC

BO_ 2332356254 M2P_SUMDATA4__14: 8 MBMU
 SG_ M2P_SysMaxVolt_14 : 0|16@1+ (1,0) [0|65535] "mV"  PC
 SG_ M2P_SysMinVolt_14 : 16|16@1+ (1,0) [0|65535] "mV"  PC
 SG_ M2P_SysAvgVolt_14 : 32|16@1+ (1,0) [0|65535] "mV"  PC
 SG_ M2P_Evn_T4_14 : 48|8@1+ (1,-50) [-50|205] "℃"  PC
 SG_ M2P_Bat_CorrectState_Require_14 : 56|8@1+ (1,0) [0|255] ""  PC

BO_ 2332356255 M2P_SUMDATA4__15: 8 MBMU
 SG_ M2P_SysMaxVolt_15 : 0|16@1+ (1,0) [0|65535] "mV"  PC
 SG_ M2P_SysMinVolt_15 : 16|16@1+ (1,0) [0|65535] "mV"  PC
 SG_ M2P_SysAvgVolt_15 : 32|16@1+ (1,0) [0|65535] "mV"  PC
 SG_ M2P_Evn_T4_15 : 48|8@1+ (1,-50) [-50|205] "℃"  PC
 SG_ M2P_Bat_CorrectState_Require_15 : 56|8@1+ (1,0) [0|255] ""  PC

BO_ 2332356256 M2P_SUMDATA4__16: 8 MBMU
 SG_ M2P_SysMaxVolt_16 : 0|16@1+ (1,0) [0|65535] "mV"  PC
 SG_ M2P_SysMinVolt_16 : 16|16@1+ (1,0) [0|65535] "mV"  PC
 SG_ M2P_SysAvgVolt_16 : 32|16@1+ (1,0) [0|65535] "mV"  PC
 SG_ M2P_Evn_T4_16 : 48|8@1+ (1,-50) [-50|205] "℃"  PC
 SG_ M2P_Bat_CorrectState_Require_16 : 56|8@1+ (1,0) [0|255] ""  PC

BO_ 2332356257 M2P_SUMDATA4__17: 8 MBMU
 SG_ M2P_SysMaxVolt_17 : 0|16@1+ (1,0) [0|65535] "mV"  PC
 SG_ M2P_SysMinVolt_17 : 16|16@1+ (1,0) [0|65535] "mV"  PC
 SG_ M2P_SysAvgVolt_17 : 32|16@1+ (1,0) [0|65535] "mV"  PC
 SG_ M2P_Evn_T4_17 : 48|8@1+ (1,-50) [-50|205] "℃"  PC
 SG_ M2P_Bat_CorrectState_Require_17 : 56|8@1+ (1,0) [0|255] ""  PC

BO_ 2332356258 M2P_SUMDATA4__18: 8 MBMU
 SG_ M2P_SysMaxVolt_18 : 0|16@1+ (1,0) [0|65535] "mV"  PC
 SG_ M2P_SysMinVolt_18 : 16|16@1+ (1,0) [0|65535] "mV"  PC
 SG_ M2P_SysAvgVolt_18 : 32|16@1+ (1,0) [0|65535] "mV"  PC
 SG_ M2P_Evn_T4_18 : 48|8@1+ (1,-50) [-50|205] "℃"  PC
 SG_ M2P_Bat_CorrectState_Require_18 : 56|8@1+ (1,0) [0|255] ""  PC

BO_ 2332356259 M2P_SUMDATA4__19: 8 MBMU
 SG_ M2P_SysMaxVolt_19 : 0|16@1+ (1,0) [0|65535] "mV"  PC
 SG_ M2P_SysMinVolt_19 : 16|16@1+ (1,0) [0|65535] "mV"  PC
 SG_ M2P_SysAvgVolt_19 : 32|16@1+ (1,0) [0|65535] "mV"  PC
 SG_ M2P_Evn_T4_19 : 48|8@1+ (1,-50) [-50|205] "℃"  PC
 SG_ M2P_Bat_CorrectState_Require_19 : 56|8@1+ (1,0) [0|255] ""  PC

BO_ 2332356260 M2P_SUMDATA4__20: 8 MBMU
 SG_ M2P_SysMaxVolt_20 : 0|16@1+ (1,0) [0|65535] "mV"  PC
 SG_ M2P_SysMinVolt_20 : 16|16@1+ (1,0) [0|65535] "mV"  PC
 SG_ M2P_SysAvgVolt_20 : 32|16@1+ (1,0) [0|65535] "mV"  PC
 SG_ M2P_Evn_T4_20 : 48|8@1+ (1,-50) [-50|205] "℃"  PC
 SG_ M2P_Bat_CorrectState_Require_20 : 56|8@1+ (1,0) [0|255] ""  PC

BO_ 2332356261 M2P_SUMDATA4__21: 8 MBMU
 SG_ M2P_SysMaxVolt_21 : 0|16@1+ (1,0) [0|65535] "mV"  PC
 SG_ M2P_SysMinVolt_21 : 16|16@1+ (1,0) [0|65535] "mV"  PC
 SG_ M2P_SysAvgVolt_21 : 32|16@1+ (1,0) [0|65535] "mV"  PC
 SG_ M2P_Evn_T4_21 : 48|8@1+ (1,-50) [-50|205] "℃"  PC
 SG_ M2P_Bat_CorrectState_Require_21 : 56|8@1+ (1,0) [0|255] ""  PC

BO_ 2332356262 M2P_SUMDATA4__22: 8 MBMU
 SG_ M2P_SysMaxVolt_22 : 0|16@1+ (1,0) [0|65535] "mV"  PC
 SG_ M2P_SysMinVolt_22 : 16|16@1+ (1,0) [0|65535] "mV"  PC
 SG_ M2P_SysAvgVolt_22 : 32|16@1+ (1,0) [0|65535] "mV"  PC
 SG_ M2P_Evn_T4_22 : 48|8@1+ (1,-50) [-50|205] "℃"  PC
 SG_ M2P_Bat_CorrectState_Require_22 : 56|8@1+ (1,0) [0|255] ""  PC

BO_ 2332356263 M2P_SUMDATA4__23: 8 MBMU
 SG_ M2P_SysMaxVolt_23 : 0|16@1+ (1,0) [0|65535] "mV"  PC
 SG_ M2P_SysMinVolt_23 : 16|16@1+ (1,0) [0|65535] "mV"  PC
 SG_ M2P_SysAvgVolt_23 : 32|16@1+ (1,0) [0|65535] "mV"  PC
 SG_ M2P_Evn_T4_23 : 48|8@1+ (1,-50) [-50|205] "℃"  PC
 SG_ M2P_Bat_CorrectState_Require_23 : 56|8@1+ (1,0) [0|255] ""  PC

BO_ 2332356264 M2P_SUMDATA4__24: 8 MBMU
 SG_ M2P_SysMaxVolt_24 : 0|16@1+ (1,0) [0|65535] "mV"  PC
 SG_ M2P_SysMinVolt_24 : 16|16@1+ (1,0) [0|65535] "mV"  PC
 SG_ M2P_SysAvgVolt_24 : 32|16@1+ (1,0) [0|65535] "mV"  PC
 SG_ M2P_Evn_T4_24 : 48|8@1+ (1,-50) [-50|205] "℃"  PC
 SG_ M2P_Bat_CorrectState_Require_24 : 56|8@1+ (1,0) [0|255] ""  PC

BO_ 2332356265 M2P_SUMDATA4__25: 8 MBMU
 SG_ M2P_SysMaxVolt_25 : 0|16@1+ (1,0) [0|65535] "mV"  PC
 SG_ M2P_SysMinVolt_25 : 16|16@1+ (1,0) [0|65535] "mV"  PC
 SG_ M2P_SysAvgVolt_25 : 32|16@1+ (1,0) [0|65535] "mV"  PC
 SG_ M2P_Evn_T4_25 : 48|8@1+ (1,-50) [-50|205] "℃"  PC
 SG_ M2P_Bat_CorrectState_Require_25 : 56|8@1+ (1,0) [0|255] ""  PC

BO_ 2332356266 M2P_SUMDATA4__26: 8 MBMU
 SG_ M2P_SysMaxVolt_26 : 0|16@1+ (1,0) [0|65535] "mV"  PC
 SG_ M2P_SysMinVolt_26 : 16|16@1+ (1,0) [0|65535] "mV"  PC
 SG_ M2P_SysAvgVolt_26 : 32|16@1+ (1,0) [0|65535] "mV"  PC
 SG_ M2P_Evn_T4_26 : 48|8@1+ (1,-50) [-50|205] "℃"  PC
 SG_ M2P_Bat_CorrectState_Require_26 : 56|8@1+ (1,0) [0|255] ""  PC

BO_ 2332356267 M2P_SUMDATA4__27: 8 MBMU
 SG_ M2P_SysMaxVolt_27 : 0|16@1+ (1,0) [0|65535] "mV"  PC
 SG_ M2P_SysMinVolt_27 : 16|16@1+ (1,0) [0|65535] "mV"  PC
 SG_ M2P_SysAvgVolt_27 : 32|16@1+ (1,0) [0|65535] "mV"  PC
 SG_ M2P_Evn_T4_27 : 48|8@1+ (1,-50) [-50|205] "℃"  PC
 SG_ M2P_Bat_CorrectState_Require_27 : 56|8@1+ (1,0) [0|255] ""  PC

BO_ 2332356268 M2P_SUMDATA4__28: 8 MBMU
 SG_ M2P_SysMaxVolt_28 : 0|16@1+ (1,0) [0|65535] "mV"  PC
 SG_ M2P_SysMinVolt_28 : 16|16@1+ (1,0) [0|65535] "mV"  PC
 SG_ M2P_SysAvgVolt_28 : 32|16@1+ (1,0) [0|65535] "mV"  PC
 SG_ M2P_Evn_T4_28 : 48|8@1+ (1,-50) [-50|205] "℃"  PC
 SG_ M2P_Bat_CorrectState_Require_28 : 56|8@1+ (1,0) [0|255] ""  PC

BO_ 2332356269 M2P_SUMDATA4__29: 8 MBMU
 SG_ M2P_SysMaxVolt_29 : 0|16@1+ (1,0) [0|65535] "mV"  PC
 SG_ M2P_SysMinVolt_29 : 16|16@1+ (1,0) [0|65535] "mV"  PC
 SG_ M2P_SysAvgVolt_29 : 32|16@1+ (1,0) [0|65535] "mV"  PC
 SG_ M2P_Evn_T4_29 : 48|8@1+ (1,-50) [-50|205] "℃"  PC
 SG_ M2P_Bat_CorrectState_Require_29 : 56|8@1+ (1,0) [0|255] ""  PC

BO_ 2332356270 M2P_SUMDATA4__30: 8 MBMU
 SG_ M2P_SysMaxVolt_30 : 0|16@1+ (1,0) [0|65535] "mV"  PC
 SG_ M2P_SysMinVolt_30 : 16|16@1+ (1,0) [0|65535] "mV"  PC
 SG_ M2P_SysAvgVolt_30 : 32|16@1+ (1,0) [0|65535] "mV"  PC
 SG_ M2P_Evn_T4_30 : 48|8@1+ (1,-50) [-50|205] "℃"  PC
 SG_ M2P_Bat_CorrectState_Require_30 : 56|8@1+ (1,0) [0|255] ""  PC

BO_ 2332356271 M2P_SUMDATA4__31: 8 MBMU
 SG_ M2P_SysMaxVolt_31 : 0|16@1+ (1,0) [0|65535] "mV"  PC
 SG_ M2P_SysMinVolt_31 : 16|16@1+ (1,0) [0|65535] "mV"  PC
 SG_ M2P_SysAvgVolt_31 : 32|16@1+ (1,0) [0|65535] "mV"  PC
 SG_ M2P_Evn_T4_31 : 48|8@1+ (1,-50) [-50|205] "℃"  PC
 SG_ M2P_Bat_CorrectState_Require_31 : 56|8@1+ (1,0) [0|255] ""  PC

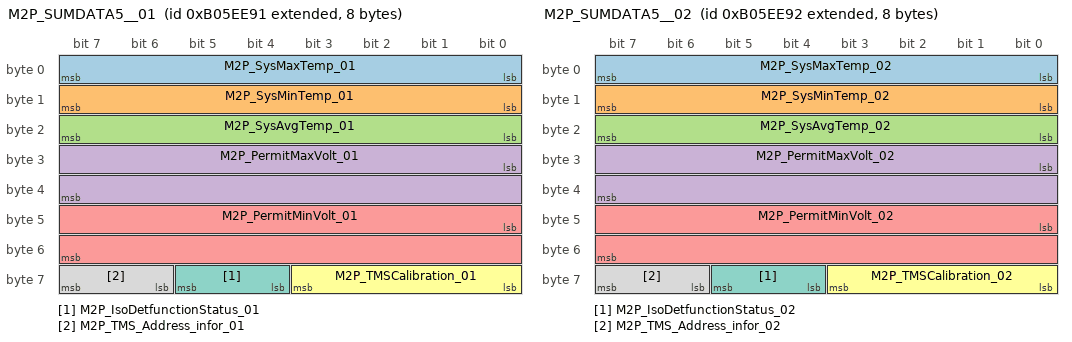
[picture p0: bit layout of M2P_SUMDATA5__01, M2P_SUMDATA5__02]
BO_ 2332421777 M2P_SUMDATA5__01: 8 MBMU
 SG_ M2P_SysMaxTemp_01 : 0|8@1+ (1,-50) [0|205] "℃"  PC
 SG_ M2P_SysMinTemp_01 : 8|8@1+ (1,-50) [0|205] "℃"  PC
 SG_ M2P_SysAvgTemp_01 : 16|8@1+ (1,-50) [0|205] "℃"  PC
 SG_ M2P_PermitMaxVolt_01 : 24|16@1+ (0.1,0) [0|6553.5] "V"  PC
 SG_ M2P_PermitMinVolt_01 : 40|16@1+ (0.1,0) [0|6553.5] "V"  PC
 SG_ M2P_TMSCalibration_01 : 56|4@1+ (1,0) [0|16] ""  PC
 SG_ M2P_IsoDetfunctionStatus_01 : 60|2@1+ (1,0) [0|3] ""  PC
 SG_ M2P_TMS_Address_infor_01 : 62|2@1+ (1,0) [0|16] "0"  PC

BO_ 2332421778 M2P_SUMDATA5__02: 8 MBMU
 SG_ M2P_SysMaxTemp_02 : 0|8@1+ (1,-50) [0|205] "℃"  PC
 SG_ M2P_SysMinTemp_02 : 8|8@1+ (1,-50) [0|205] "℃"  PC
 SG_ M2P_SysAvgTemp_02 : 16|8@1+ (1,-50) [0|205] "℃"  PC
 SG_ M2P_PermitMaxVolt_02 : 24|16@1+ (0.1,0) [0|6553.5] "V"  PC
 SG_ M2P_PermitMinVolt_02 : 40|16@1+ (0.1,0) [0|6553.5] "V"  PC
 SG_ M2P_TMSCalibration_02 : 56|4@1+ (1,0) [0|16] ""  PC
 SG_ M2P_IsoDetfunctionStatus_02 : 60|2@1+ (1,0) [0|3] ""  PC
 SG_ M2P_TMS_Address_infor_02 : 62|2@1+ (1,0) [0|16] "0"  PC

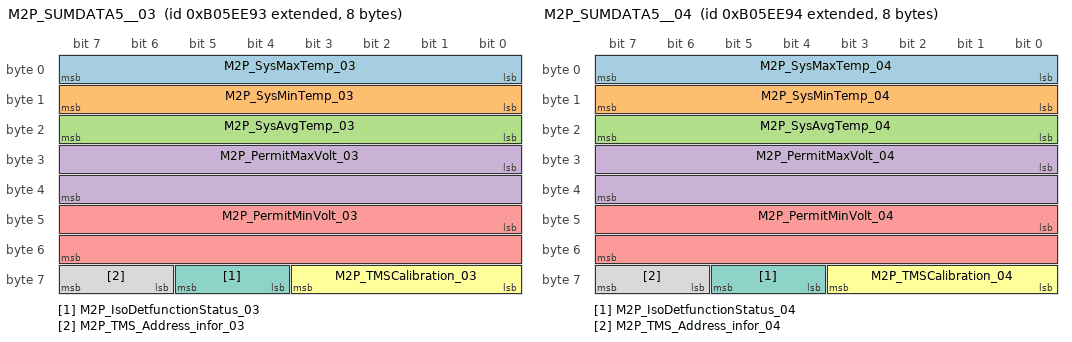
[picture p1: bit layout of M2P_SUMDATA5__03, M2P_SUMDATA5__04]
BO_ 2332421779 M2P_SUMDATA5__03: 8 MBMU
 SG_ M2P_SysMaxTemp_03 : 0|8@1+ (1,-50) [0|205] "℃"  PC
 SG_ M2P_SysMinTemp_03 : 8|8@1+ (1,-50) [0|205] "℃"  PC
 SG_ M2P_SysAvgTemp_03 : 16|8@1+ (1,-50) [0|205] "℃"  PC
 SG_ M2P_PermitMaxVolt_03 : 24|16@1+ (0.1,0) [0|6553.5] "V"  PC
 SG_ M2P_PermitMinVolt_03 : 40|16@1+ (0.1,0) [0|6553.5] "V"  PC
 SG_ M2P_TMSCalibration_03 : 56|4@1+ (1,0) [0|16] ""  PC
 SG_ M2P_IsoDetfunctionStatus_03 : 60|2@1+ (1,0) [0|3] ""  PC
 SG_ M2P_TMS_Address_infor_03 : 62|2@1+ (1,0) [0|16] "0"  PC

BO_ 2332421780 M2P_SUMDATA5__04: 8 MBMU
 SG_ M2P_SysMaxTemp_04 : 0|8@1+ (1,-50) [0|205] "℃"  PC
 SG_ M2P_SysMinTemp_04 : 8|8@1+ (1,-50) [0|205] "℃"  PC
 SG_ M2P_SysAvgTemp_04 : 16|8@1+ (1,-50) [0|205] "℃"  PC
 SG_ M2P_PermitMaxVolt_04 : 24|16@1+ (0.1,0) [0|6553.5] "V"  PC
 SG_ M2P_PermitMinVolt_04 : 40|16@1+ (0.1,0) [0|6553.5] "V"  PC
 SG_ M2P_TMSCalibration_04 : 56|4@1+ (1,0) [0|16] ""  PC
 SG_ M2P_IsoDetfunctionStatus_04 : 60|2@1+ (1,0) [0|3] ""  PC
 SG_ M2P_TMS_Address_infor_04 : 62|2@1+ (1,0) [0|16] "0"  PC

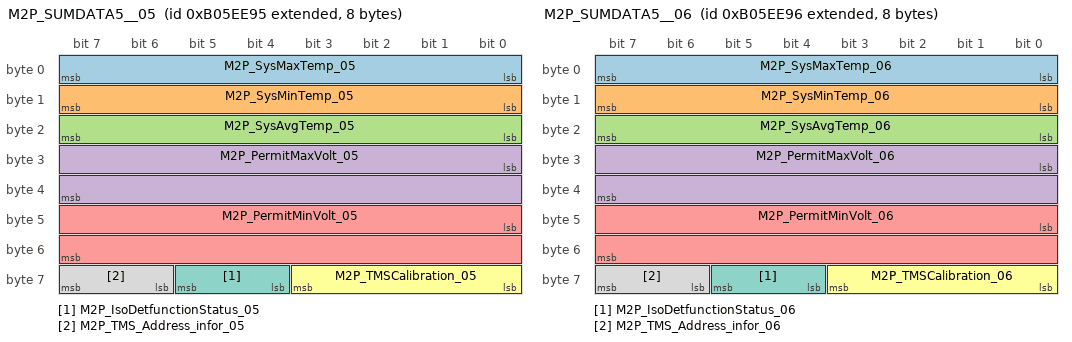
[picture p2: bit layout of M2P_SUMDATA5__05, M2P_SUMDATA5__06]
BO_ 2332421781 M2P_SUMDATA5__05: 8 MBMU
 SG_ M2P_SysMaxTemp_05 : 0|8@1+ (1,-50) [0|205] "℃"  PC
 SG_ M2P_SysMinTemp_05 : 8|8@1+ (1,-50) [0|205] "℃"  PC
 SG_ M2P_SysAvgTemp_05 : 16|8@1+ (1,-50) [0|205] "℃"  PC
 SG_ M2P_PermitMaxVolt_05 : 24|16@1+ (0.1,0) [0|6553.5] "V"  PC
 SG_ M2P_PermitMinVolt_05 : 40|16@1+ (0.1,0) [0|6553.5] "V"  PC
 SG_ M2P_TMSCalibration_05 : 56|4@1+ (1,0) [0|16] ""  PC
 SG_ M2P_IsoDetfunctionStatus_05 : 60|2@1+ (1,0) [0|3] ""  PC
 SG_ M2P_TMS_Address_infor_05 : 62|2@1+ (1,0) [0|16] "0"  PC

BO_ 2332421782 M2P_SUMDATA5__06: 8 MBMU
 SG_ M2P_SysMaxTemp_06 : 0|8@1+ (1,-50) [0|205] "℃"  PC
 SG_ M2P_SysMinTemp_06 : 8|8@1+ (1,-50) [0|205] "℃"  PC
 SG_ M2P_SysAvgTemp_06 : 16|8@1+ (1,-50) [0|205] "℃"  PC
 SG_ M2P_PermitMaxVolt_06 : 24|16@1+ (0.1,0) [0|6553.5] "V"  PC
 SG_ M2P_PermitMinVolt_06 : 40|16@1+ (0.1,0) [0|6553.5] "V"  PC
 SG_ M2P_TMSCalibration_06 : 56|4@1+ (1,0) [0|16] ""  PC
 SG_ M2P_IsoDetfunctionStatus_06 : 60|2@1+ (1,0) [0|3] ""  PC
 SG_ M2P_TMS_Address_infor_06 : 62|2@1+ (1,0) [0|16] "0"  PC

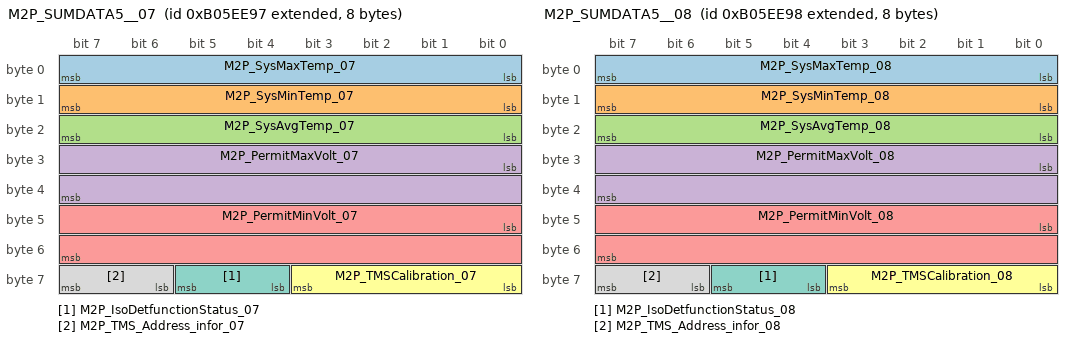
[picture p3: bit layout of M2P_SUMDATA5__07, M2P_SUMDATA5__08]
BO_ 2332421783 M2P_SUMDATA5__07: 8 MBMU
 SG_ M2P_SysMaxTemp_07 : 0|8@1+ (1,-50) [0|205] "℃"  PC
 SG_ M2P_SysMinTemp_07 : 8|8@1+ (1,-50) [0|205] "℃"  PC
 SG_ M2P_SysAvgTemp_07 : 16|8@1+ (1,-50) [0|205] "℃"  PC
 SG_ M2P_PermitMaxVolt_07 : 24|16@1+ (0.1,0) [0|6553.5] "V"  PC
 SG_ M2P_PermitMinVolt_07 : 40|16@1+ (0.1,0) [0|6553.5] "V"  PC
 SG_ M2P_TMSCalibration_07 : 56|4@1+ (1,0) [0|16] ""  PC
 SG_ M2P_IsoDetfunctionStatus_07 : 60|2@1+ (1,0) [0|3] ""  PC
 SG_ M2P_TMS_Address_infor_07 : 62|2@1+ (1,0) [0|16] "0"  PC

BO_ 2332421784 M2P_SUMDATA5__08: 8 MBMU
 SG_ M2P_SysMaxTemp_08 : 0|8@1+ (1,-50) [0|205] "℃"  PC
 SG_ M2P_SysMinTemp_08 : 8|8@1+ (1,-50) [0|205] "℃"  PC
 SG_ M2P_SysAvgTemp_08 : 16|8@1+ (1,-50) [0|205] "℃"  PC
 SG_ M2P_PermitMaxVolt_08 : 24|16@1+ (0.1,0) [0|6553.5] "V"  PC
 SG_ M2P_PermitMinVolt_08 : 40|16@1+ (0.1,0) [0|6553.5] "V"  PC
 SG_ M2P_TMSCalibration_08 : 56|4@1+ (1,0) [0|16] ""  PC
 SG_ M2P_IsoDetfunctionStatus_08 : 60|2@1+ (1,0) [0|3] ""  PC
 SG_ M2P_TMS_Address_infor_08 : 62|2@1+ (1,0) [0|16] "0"  PC

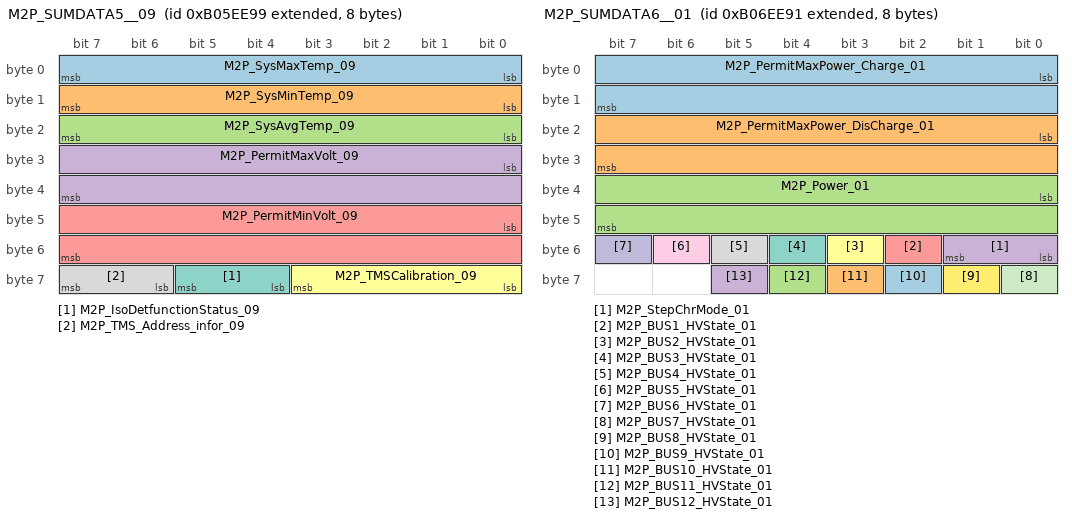
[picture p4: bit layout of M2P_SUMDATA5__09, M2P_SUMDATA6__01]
BO_ 2332421785 M2P_SUMDATA5__09: 8 MBMU
 SG_ M2P_SysMaxTemp_09 : 0|8@1+ (1,-50) [0|205] "℃"  PC
 SG_ M2P_SysMinTemp_09 : 8|8@1+ (1,-50) [0|205] "℃"  PC
 SG_ M2P_SysAvgTemp_09 : 16|8@1+ (1,-50) [0|205] "℃"  PC
 SG_ M2P_PermitMaxVolt_09 : 24|16@1+ (0.1,0) [0|6553.5] "V"  PC
 SG_ M2P_PermitMinVolt_09 : 40|16@1+ (0.1,0) [0|6553.5] "V"  PC
 SG_ M2P_TMSCalibration_09 : 56|4@1+ (1,0) [0|16] ""  PC
 SG_ M2P_IsoDetfunctionStatus_09 : 60|2@1+ (1,0) [0|3] ""  PC
 SG_ M2P_TMS_Address_infor_09 : 62|2@1+ (1,0) [0|16] "0"  PC

BO_ 2332421786 M2P_SUMDATA5__10: 8 MBMU
 SG_ M2P_SysMaxTemp_10 : 0|8@1+ (1,-50) [0|205] "℃"  PC
 SG_ M2P_SysMinTemp_10 : 8|8@1+ (1,-50) [0|205] "℃"  PC
 SG_ M2P_SysAvgTemp_10 : 16|8@1+ (1,-50) [0|205] "℃"  PC
 SG_ M2P_PermitMaxVolt_10 : 24|16@1+ (0.1,0) [0|6553.5] "V"  PC
 SG_ M2P_PermitMinVolt_10 : 40|16@1+ (0.1,0) [0|6553.5] "V"  PC
 SG_ M2P_TMSCalibration_10 : 56|4@1+ (1,0) [0|16] ""  PC
 SG_ M2P_IsoDetfunctionStatus_10 : 60|2@1+ (1,0) [0|3] ""  PC
 SG_ M2P_TMS_Address_infor_10 : 62|2@1+ (1,0) [0|16] "0"  PC

BO_ 2332421787 M2P_SUMDATA5__11: 8 MBMU
 SG_ M2P_SysMaxTemp_11 : 0|8@1+ (1,-50) [0|205] "℃"  PC
 SG_ M2P_SysMinTemp_11 : 8|8@1+ (1,-50) [0|205] "℃"  PC
 SG_ M2P_SysAvgTemp_11 : 16|8@1+ (1,-50) [0|205] "℃"  PC
 SG_ M2P_PermitMaxVolt_11 : 24|16@1+ (0.1,0) [0|6553.5] "V"  PC
 SG_ M2P_PermitMinVolt_11 : 40|16@1+ (0.1,0) [0|6553.5] "V"  PC
 SG_ M2P_TMSCalibration_11 : 56|4@1+ (1,0) [0|16] ""  PC
 SG_ M2P_IsoDetfunctionStatus_11 : 60|2@1+ (1,0) [0|3] ""  PC
 SG_ M2P_TMS_Address_infor_11 : 62|2@1+ (1,0) [0|16] "0"  PC

BO_ 2332421788 M2P_SUMDATA5__12: 8 MBMU
 SG_ M2P_SysMaxTemp_12 : 0|8@1+ (1,-50) [0|205] "℃"  PC
 SG_ M2P_SysMinTemp_12 : 8|8@1+ (1,-50) [0|205] "℃"  PC
 SG_ M2P_SysAvgTemp_12 : 16|8@1+ (1,-50) [0|205] "℃"  PC
 SG_ M2P_PermitMaxVolt_12 : 24|16@1+ (0.1,0) [0|6553.5] "V"  PC
 SG_ M2P_PermitMinVolt_12 : 40|16@1+ (0.1,0) [0|6553.5] "V"  PC
 SG_ M2P_TMSCalibration_12 : 56|4@1+ (1,0) [0|16] ""  PC
 SG_ M2P_IsoDetfunctionStatus_12 : 60|2@1+ (1,0) [0|3] ""  PC
 SG_ M2P_TMS_Address_infor_12 : 62|2@1+ (1,0) [0|16] "0"  PC

BO_ 2332421789 M2P_SUMDATA5__13: 8 MBMU
 SG_ M2P_SysMaxTemp_13 : 0|8@1+ (1,-50) [0|205] "℃"  PC
 SG_ M2P_SysMinTemp_13 : 8|8@1+ (1,-50) [0|205] "℃"  PC
 SG_ M2P_SysAvgTemp_13 : 16|8@1+ (1,-50) [0|205] "℃"  PC
 SG_ M2P_PermitMaxVolt_13 : 24|16@1+ (0.1,0) [0|6553.5] "V"  PC
 SG_ M2P_PermitMinVolt_13 : 40|16@1+ (0.1,0) [0|6553.5] "V"  PC
 SG_ M2P_TMSCalibration_13 : 56|4@1+ (1,0) [0|16] ""  PC
 SG_ M2P_IsoDetfunctionStatus_13 : 60|2@1+ (1,0) [0|3] ""  PC
 SG_ M2P_TMS_Address_infor_13 : 62|2@1+ (1,0) [0|16] "0"  PC

BO_ 2332421790 M2P_SUMDATA5__14: 8 MBMU
 SG_ M2P_SysMaxTemp_14 : 0|8@1+ (1,-50) [0|205] "℃"  PC
 SG_ M2P_SysMinTemp_14 : 8|8@1+ (1,-50) [0|205] "℃"  PC
 SG_ M2P_SysAvgTemp_14 : 16|8@1+ (1,-50) [0|205] "℃"  PC
 SG_ M2P_PermitMaxVolt_14 : 24|16@1+ (0.1,0) [0|6553.5] "V"  PC
 SG_ M2P_PermitMinVolt_14 : 40|16@1+ (0.1,0) [0|6553.5] "V"  PC
 SG_ M2P_TMSCalibration_14 : 56|4@1+ (1,0) [0|16] ""  PC
 SG_ M2P_IsoDetfunctionStatus_14 : 60|2@1+ (1,0) [0|3] ""  PC
 SG_ M2P_TMS_Address_infor_14 : 62|2@1+ (1,0) [0|16] "0"  PC

BO_ 2332421791 M2P_SUMDATA5__15: 8 MBMU
 SG_ M2P_SysMaxTemp_15 : 0|8@1+ (1,-50) [0|205] "℃"  PC
 SG_ M2P_SysMinTemp_15 : 8|8@1+ (1,-50) [0|205] "℃"  PC
 SG_ M2P_SysAvgTemp_15 : 16|8@1+ (1,-50) [0|205] "℃"  PC
 SG_ M2P_PermitMaxVolt_15 : 24|16@1+ (0.1,0) [0|6553.5] "V"  PC
 SG_ M2P_PermitMinVolt_15 : 40|16@1+ (0.1,0) [0|6553.5] "V"  PC
 SG_ M2P_TMSCalibration_15 : 56|4@1+ (1,0) [0|16] ""  PC
 SG_ M2P_IsoDetfunctionStatus_15 : 60|2@1+ (1,0) [0|3] ""  PC
 SG_ M2P_TMS_Address_infor_15 : 62|2@1+ (1,0) [0|16] "0"  PC

BO_ 2332421792 M2P_SUMDATA5__16: 8 MBMU
 SG_ M2P_SysMaxTemp_16 : 0|8@1+ (1,-50) [0|205] "℃"  PC
 SG_ M2P_SysMinTemp_16 : 8|8@1+ (1,-50) [0|205] "℃"  PC
 SG_ M2P_SysAvgTemp_16 : 16|8@1+ (1,-50) [0|205] "℃"  PC
 SG_ M2P_PermitMaxVolt_16 : 24|16@1+ (0.1,0) [0|6553.5] "V"  PC
 SG_ M2P_PermitMinVolt_16 : 40|16@1+ (0.1,0) [0|6553.5] "V"  PC
 SG_ M2P_TMSCalibration_16 : 56|4@1+ (1,0) [0|16] ""  PC
 SG_ M2P_IsoDetfunctionStatus_16 : 60|2@1+ (1,0) [0|3] ""  PC
 SG_ M2P_TMS_Address_infor_16 : 62|2@1+ (1,0) [0|16] "0"  PC

BO_ 2332421793 M2P_SUMDATA5__17: 8 MBMU
 SG_ M2P_SysMaxTemp_17 : 0|8@1+ (1,-50) [0|205] "℃"  PC
 SG_ M2P_SysMinTemp_17 : 8|8@1+ (1,-50) [0|205] "℃"  PC
 SG_ M2P_SysAvgTemp_17 : 16|8@1+ (1,-50) [0|205] "℃"  PC
 SG_ M2P_PermitMaxVolt_17 : 24|16@1+ (0.1,0) [0|6553.5] "V"  PC
 SG_ M2P_PermitMinVolt_17 : 40|16@1+ (0.1,0) [0|6553.5] "V"  PC
 SG_ M2P_TMSCalibration_17 : 56|4@1+ (1,0) [0|16] ""  PC
 SG_ M2P_IsoDetfunctionStatus_17 : 60|2@1+ (1,0) [0|3] ""  PC
 SG_ M2P_TMS_Address_infor_17 : 62|2@1+ (1,0) [0|16] "0"  PC

BO_ 2332421794 M2P_SUMDATA5__18: 8 MBMU
 SG_ M2P_SysMaxTemp_18 : 0|8@1+ (1,-50) [0|205] "℃"  PC
 SG_ M2P_SysMinTemp_18 : 8|8@1+ (1,-50) [0|205] "℃"  PC
 SG_ M2P_SysAvgTemp_18 : 16|8@1+ (1,-50) [0|205] "℃"  PC
 SG_ M2P_PermitMaxVolt_18 : 24|16@1+ (0.1,0) [0|6553.5] "V"  PC
 SG_ M2P_PermitMinVolt_18 : 40|16@1+ (0.1,0) [0|6553.5] "V"  PC
 SG_ M2P_TMSCalibration_18 : 56|4@1+ (1,0) [0|16] ""  PC
 SG_ M2P_IsoDetfunctionStatus_18 : 60|2@1+ (1,0) [0|3] ""  PC
 SG_ M2P_TMS_Address_infor_18 : 62|2@1+ (1,0) [0|16] "0"  PC

BO_ 2332421795 M2P_SUMDATA5__19: 8 MBMU
 SG_ M2P_SysMaxTemp_19 : 0|8@1+ (1,-50) [0|205] "℃"  PC
 SG_ M2P_SysMinTemp_19 : 8|8@1+ (1,-50) [0|205] "℃"  PC
 SG_ M2P_SysAvgTemp_19 : 16|8@1+ (1,-50) [0|205] "℃"  PC
 SG_ M2P_PermitMaxVolt_19 : 24|16@1+ (0.1,0) [0|6553.5] "V"  PC
 SG_ M2P_PermitMinVolt_19 : 40|16@1+ (0.1,0) [0|6553.5] "V"  PC
 SG_ M2P_TMSCalibration_19 : 56|4@1+ (1,0) [0|16] ""  PC
 SG_ M2P_IsoDetfunctionStatus_19 : 60|2@1+ (1,0) [0|3] ""  PC
 SG_ M2P_TMS_Address_infor_19 : 62|2@1+ (1,0) [0|16] "0"  PC

BO_ 2332421796 M2P_SUMDATA5__20: 8 MBMU
 SG_ M2P_SysMaxTemp_20 : 0|8@1+ (1,-50) [0|205] "℃"  PC
 SG_ M2P_SysMinTemp_20 : 8|8@1+ (1,-50) [0|205] "℃"  PC
 SG_ M2P_SysAvgTemp_20 : 16|8@1+ (1,-50) [0|205] "℃"  PC
 SG_ M2P_PermitMaxVolt_20 : 24|16@1+ (0.1,0) [0|6553.5] "V"  PC
 SG_ M2P_PermitMinVolt_20 : 40|16@1+ (0.1,0) [0|6553.5] "V"  PC
 SG_ M2P_TMSCalibration_20 : 56|4@1+ (1,0) [0|16] ""  PC
 SG_ M2P_IsoDetfunctionStatus_20 : 60|2@1+ (1,0) [0|3] ""  PC
 SG_ M2P_TMS_Address_infor_20 : 62|2@1+ (1,0) [0|16] "0"  PC

BO_ 2332421797 M2P_SUMDATA5__21: 8 MBMU
 SG_ M2P_SysMaxTemp_21 : 0|8@1+ (1,-50) [0|205] "℃"  PC
 SG_ M2P_SysMinTemp_21 : 8|8@1+ (1,-50) [0|205] "℃"  PC
 SG_ M2P_SysAvgTemp_21 : 16|8@1+ (1,-50) [0|205] "℃"  PC
 SG_ M2P_PermitMaxVolt_21 : 24|16@1+ (0.1,0) [0|6553.5] "V"  PC
 SG_ M2P_PermitMinVolt_21 : 40|16@1+ (0.1,0) [0|6553.5] "V"  PC
 SG_ M2P_TMSCalibration_21 : 56|4@1+ (1,0) [0|16] ""  PC
 SG_ M2P_IsoDetfunctionStatus_21 : 60|2@1+ (1,0) [0|3] ""  PC
 SG_ M2P_TMS_Address_infor_21 : 62|2@1+ (1,0) [0|16] "0"  PC

BO_ 2332421798 M2P_SUMDATA5__22: 8 MBMU
 SG_ M2P_SysMaxTemp_22 : 0|8@1+ (1,-50) [0|205] "℃"  PC
 SG_ M2P_SysMinTemp_22 : 8|8@1+ (1,-50) [0|205] "℃"  PC
 SG_ M2P_SysAvgTemp_22 : 16|8@1+ (1,-50) [0|205] "℃"  PC
 SG_ M2P_PermitMaxVolt_22 : 24|16@1+ (0.1,0) [0|6553.5] "V"  PC
 SG_ M2P_PermitMinVolt_22 : 40|16@1+ (0.1,0) [0|6553.5] "V"  PC
 SG_ M2P_TMSCalibration_22 : 56|4@1+ (1,0) [0|16] ""  PC
 SG_ M2P_IsoDetfunctionStatus_22 : 60|2@1+ (1,0) [0|3] ""  PC
 SG_ M2P_TMS_Address_infor_22 : 62|2@1+ (1,0) [0|16] "0"  PC

BO_ 2332421799 M2P_SUMDATA5__23: 8 MBMU
 SG_ M2P_SysMaxTemp_23 : 0|8@1+ (1,-50) [0|205] "℃"  PC
 SG_ M2P_SysMinTemp_23 : 8|8@1+ (1,-50) [0|205] "℃"  PC
 SG_ M2P_SysAvgTemp_23 : 16|8@1+ (1,-50) [0|205] "℃"  PC
 SG_ M2P_PermitMaxVolt_23 : 24|16@1+ (0.1,0) [0|6553.5] "V"  PC
 SG_ M2P_PermitMinVolt_23 : 40|16@1+ (0.1,0) [0|6553.5] "V"  PC
 SG_ M2P_TMSCalibration_23 : 56|4@1+ (1,0) [0|16] ""  PC
 SG_ M2P_IsoDetfunctionStatus_23 : 60|2@1+ (1,0) [0|3] ""  PC
 SG_ M2P_TMS_Address_infor_23 : 62|2@1+ (1,0) [0|16] "0"  PC

BO_ 2332421800 M2P_SUMDATA5__24: 8 MBMU
 SG_ M2P_SysMaxTemp_24 : 0|8@1+ (1,-50) [0|205] "℃"  PC
 SG_ M2P_SysMinTemp_24 : 8|8@1+ (1,-50) [0|205] "℃"  PC
 SG_ M2P_SysAvgTemp_24 : 16|8@1+ (1,-50) [0|205] "℃"  PC
 SG_ M2P_PermitMaxVolt_24 : 24|16@1+ (0.1,0) [0|6553.5] "V"  PC
 SG_ M2P_PermitMinVolt_24 : 40|16@1+ (0.1,0) [0|6553.5] "V"  PC
 SG_ M2P_TMSCalibration_24 : 56|4@1+ (1,0) [0|16] ""  PC
 SG_ M2P_IsoDetfunctionStatus_24 : 60|2@1+ (1,0) [0|3] ""  PC
 SG_ M2P_TMS_Address_infor_24 : 62|2@1+ (1,0) [0|16] "0"  PC

BO_ 2332421801 M2P_SUMDATA5__25: 8 MBMU
 SG_ M2P_SysMaxTemp_25 : 0|8@1+ (1,-50) [0|205] "℃"  PC
 SG_ M2P_SysMinTemp_25 : 8|8@1+ (1,-50) [0|205] "℃"  PC
 SG_ M2P_SysAvgTemp_25 : 16|8@1+ (1,-50) [0|205] "℃"  PC
 SG_ M2P_PermitMaxVolt_25 : 24|16@1+ (0.1,0) [0|6553.5] "V"  PC
 SG_ M2P_PermitMinVolt_25 : 40|16@1+ (0.1,0) [0|6553.5] "V"  PC
 SG_ M2P_TMSCalibration_25 : 56|4@1+ (1,0) [0|16] ""  PC
 SG_ M2P_IsoDetfunctionStatus_25 : 60|2@1+ (1,0) [0|3] ""  PC
 SG_ M2P_TMS_Address_infor_25 : 62|2@1+ (1,0) [0|16] "0"  PC

BO_ 2332421802 M2P_SUMDATA5__26: 8 MBMU
 SG_ M2P_SysMaxTemp_26 : 0|8@1+ (1,-50) [0|205] "℃"  PC
 SG_ M2P_SysMinTemp_26 : 8|8@1+ (1,-50) [0|205] "℃"  PC
 SG_ M2P_SysAvgTemp_26 : 16|8@1+ (1,-50) [0|205] "℃"  PC
 SG_ M2P_PermitMaxVolt_26 : 24|16@1+ (0.1,0) [0|6553.5] "V"  PC
 SG_ M2P_PermitMinVolt_26 : 40|16@1+ (0.1,0) [0|6553.5] "V"  PC
 SG_ M2P_TMSCalibration_26 : 56|4@1+ (1,0) [0|16] ""  PC
 SG_ M2P_IsoDetfunctionStatus_26 : 60|2@1+ (1,0) [0|3] ""  PC
 SG_ M2P_TMS_Address_infor_26 : 62|2@1+ (1,0) [0|16] "0"  PC

BO_ 2332421803 M2P_SUMDATA5__27: 8 MBMU
 SG_ M2P_SysMaxTemp_27 : 0|8@1+ (1,-50) [0|205] "℃"  PC
 SG_ M2P_SysMinTemp_27 : 8|8@1+ (1,-50) [0|205] "℃"  PC
 SG_ M2P_SysAvgTemp_27 : 16|8@1+ (1,-50) [0|205] "℃"  PC
 SG_ M2P_PermitMaxVolt_27 : 24|16@1+ (0.1,0) [0|6553.5] "V"  PC
 SG_ M2P_PermitMinVolt_27 : 40|16@1+ (0.1,0) [0|6553.5] "V"  PC
 SG_ M2P_TMSCalibration_27 : 56|4@1+ (1,0) [0|16] ""  PC
 SG_ M2P_IsoDetfunctionStatus_27 : 60|2@1+ (1,0) [0|3] ""  PC
 SG_ M2P_TMS_Address_infor_27 : 62|2@1+ (1,0) [0|16] "0"  PC

BO_ 2332421804 M2P_SUMDATA5__28: 8 MBMU
 SG_ M2P_SysMaxTemp_28 : 0|8@1+ (1,-50) [0|205] "℃"  PC
 SG_ M2P_SysMinTemp_28 : 8|8@1+ (1,-50) [0|205] "℃"  PC
 SG_ M2P_SysAvgTemp_28 : 16|8@1+ (1,-50) [0|205] "℃"  PC
 SG_ M2P_PermitMaxVolt_28 : 24|16@1+ (0.1,0) [0|6553.5] "V"  PC
 SG_ M2P_PermitMinVolt_28 : 40|16@1+ (0.1,0) [0|6553.5] "V"  PC
 SG_ M2P_TMSCalibration_28 : 56|4@1+ (1,0) [0|16] ""  PC
 SG_ M2P_IsoDetfunctionStatus_28 : 60|2@1+ (1,0) [0|3] ""  PC
 SG_ M2P_TMS_Address_infor_28 : 62|2@1+ (1,0) [0|16] "0"  PC

BO_ 2332421805 M2P_SUMDATA5__29: 8 MBMU
 SG_ M2P_SysMaxTemp_29 : 0|8@1+ (1,-50) [0|205] "℃"  PC
 SG_ M2P_SysMinTemp_29 : 8|8@1+ (1,-50) [0|205] "℃"  PC
 SG_ M2P_SysAvgTemp_29 : 16|8@1+ (1,-50) [0|205] "℃"  PC
 SG_ M2P_PermitMaxVolt_29 : 24|16@1+ (0.1,0) [0|6553.5] "V"  PC
 SG_ M2P_PermitMinVolt_29 : 40|16@1+ (0.1,0) [0|6553.5] "V"  PC
 SG_ M2P_TMSCalibration_29 : 56|4@1+ (1,0) [0|16] ""  PC
 SG_ M2P_IsoDetfunctionStatus_29 : 60|2@1+ (1,0) [0|3] ""  PC
 SG_ M2P_TMS_Address_infor_29 : 62|2@1+ (1,0) [0|16] "0"  PC

BO_ 2332421806 M2P_SUMDATA5__30: 8 MBMU
 SG_ M2P_SysMaxTemp_30 : 0|8@1+ (1,-50) [0|205] "℃"  PC
 SG_ M2P_SysMinTemp_30 : 8|8@1+ (1,-50) [0|205] "℃"  PC
 SG_ M2P_SysAvgTemp_30 : 16|8@1+ (1,-50) [0|205] "℃"  PC
 SG_ M2P_PermitMaxVolt_30 : 24|16@1+ (0.1,0) [0|6553.5] "V"  PC
 SG_ M2P_PermitMinVolt_30 : 40|16@1+ (0.1,0) [0|6553.5] "V"  PC
 SG_ M2P_TMSCalibration_30 : 56|4@1+ (1,0) [0|16] ""  PC
 SG_ M2P_IsoDetfunctionStatus_30 : 60|2@1+ (1,0) [0|3] ""  PC
 SG_ M2P_TMS_Address_infor_30 : 62|2@1+ (1,0) [0|16] "0"  PC

BO_ 2332421807 M2P_SUMDATA5__31: 8 MBMU
 SG_ M2P_SysMaxTemp_31 : 0|8@1+ (1,-50) [0|205] "℃"  PC
 SG_ M2P_SysMinTemp_31 : 8|8@1+ (1,-50) [0|205] "℃"  PC
 SG_ M2P_SysAvgTemp_31 : 16|8@1+ (1,-50) [0|205] "℃"  PC
 SG_ M2P_PermitMaxVolt_31 : 24|16@1+ (0.1,0) [0|6553.5] "V"  PC
 SG_ M2P_PermitMinVolt_31 : 40|16@1+ (0.1,0) [0|6553.5] "V"  PC
 SG_ M2P_TMSCalibration_31 : 56|4@1+ (1,0) [0|16] ""  PC
 SG_ M2P_IsoDetfunctionStatus_31 : 60|2@1+ (1,0) [0|3] ""  PC
 SG_ M2P_TMS_Address_infor_31 : 62|2@1+ (1,0) [0|16] "0"  PC

BO_ 2332487313 M2P_SUMDATA6__01: 8 MBMU
 SG_ M2P_PermitMaxPower_Charge_01 : 0|16@1+ (1,-20000) [0|45535] "Kw"  PC
 SG_ M2P_PermitMaxPower_DisCharge_01 : 16|16@1+ (1,-20000) [0|45535] "Kw"  PC
 SG_ M2P_Power_01 : 32|16@1+ (1,-20000) [0|45535] "Kw"  PC
 SG_ M2P_StepChrMode_01 : 48|2@1+ (1,0) [0|3] ""  PC
 SG_ M2P_BUS1_HVState_01 : 50|1@1+ (1,0) [0|1] ""  PC,SBMU
 SG_ M2P_BUS2_HVState_01 : 51|1@1+ (1,0) [0|1] ""  PC,SBMU
 SG_ M2P_BUS3_HVState_01 : 52|1@1+ (1,0) [0|1] ""  PC,SBMU
 SG_ M2P_BUS4_HVState_01 : 53|1@1+ (1,0) [0|1] ""  PC,SBMU
 SG_ M2P_BUS5_HVState_01 : 54|1@1+ (1,0) [0|1] ""  PC,SBMU
 SG_ M2P_BUS6_HVState_01 : 55|1@1+ (1,0) [0|1] ""  PC,SBMU
 SG_ M2P_BUS7_HVState_01 : 56|1@1+ (1,0) [0|1] ""  PC,SBMU
 SG_ M2P_BUS8_HVState_01 : 57|1@1+ (1,0) [0|1] ""  PC,SBMU
 SG_ M2P_BUS9_HVState_01 : 58|1@1+ (1,0) [0|1] ""  PC,SBMU
 SG_ M2P_BUS10_HVState_01 : 59|1@1+ (1,0) [0|1] ""  PC,SBMU
 SG_ M2P_BUS11_HVState_01 : 60|1@1+ (1,0) [0|1] ""  PC,SBMU
 SG_ M2P_BUS12_HVState_01 : 61|1@1+ (1,0) [0|1] ""  PC,SBMU

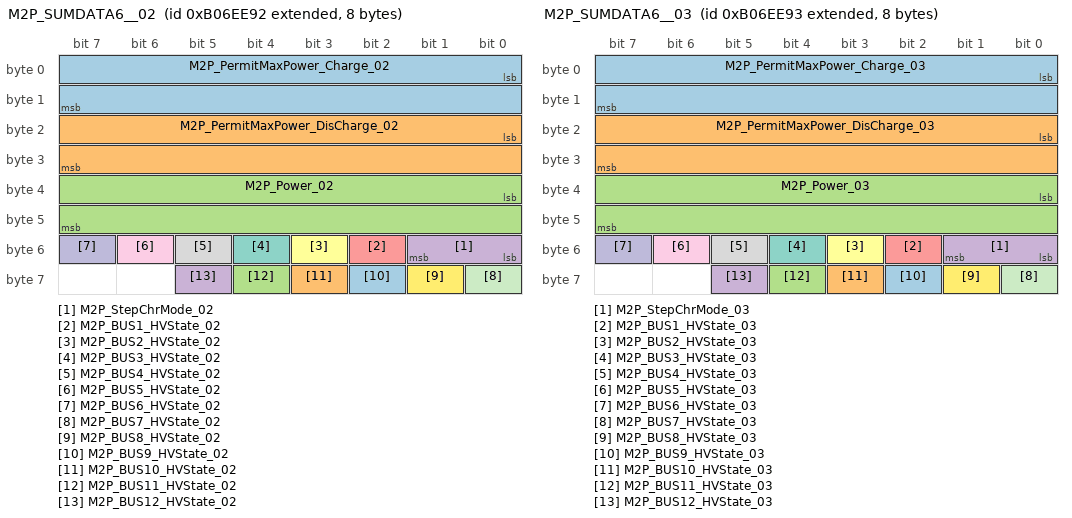
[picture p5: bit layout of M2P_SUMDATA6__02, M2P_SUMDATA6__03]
BO_ 2332487314 M2P_SUMDATA6__02: 8 MBMU
 SG_ M2P_PermitMaxPower_Charge_02 : 0|16@1+ (1,-20000) [0|45535] "Kw"  PC
 SG_ M2P_PermitMaxPower_DisCharge_02 : 16|16@1+ (1,-20000) [0|45535] "Kw"  PC
 SG_ M2P_Power_02 : 32|16@1+ (1,-20000) [0|45535] "Kw"  PC
 SG_ M2P_StepChrMode_02 : 48|2@1+ (1,0) [0|3] ""  PC
 SG_ M2P_BUS1_HVState_02 : 50|1@1+ (1,0) [0|1] ""  PC,SBMU
 SG_ M2P_BUS2_HVState_02 : 51|1@1+ (1,0) [0|1] ""  PC,SBMU
 SG_ M2P_BUS3_HVState_02 : 52|1@1+ (1,0) [0|1] ""  PC,SBMU
 SG_ M2P_BUS4_HVState_02 : 53|1@1+ (1,0) [0|1] ""  PC,SBMU
 SG_ M2P_BUS5_HVState_02 : 54|1@1+ (1,0) [0|1] ""  PC,SBMU
 SG_ M2P_BUS6_HVState_02 : 55|1@1+ (1,0) [0|1] ""  PC,SBMU
 SG_ M2P_BUS7_HVState_02 : 56|1@1+ (1,0) [0|1] ""  PC,SBMU
 SG_ M2P_BUS8_HVState_02 : 57|1@1+ (1,0) [0|1] ""  PC,SBMU
 SG_ M2P_BUS9_HVState_02 : 58|1@1+ (1,0) [0|1] ""  PC,SBMU
 SG_ M2P_BUS10_HVState_02 : 59|1@1+ (1,0) [0|1] ""  PC,SBMU
 SG_ M2P_BUS11_HVState_02 : 60|1@1+ (1,0) [0|1] ""  PC,SBMU
 SG_ M2P_BUS12_HVState_02 : 61|1@1+ (1,0) [0|1] ""  PC,SBMU

BO_ 2332487315 M2P_SUMDATA6__03: 8 MBMU
 SG_ M2P_PermitMaxPower_Charge_03 : 0|16@1+ (1,-20000) [0|45535] "Kw"  PC
 SG_ M2P_PermitMaxPower_DisCharge_03 : 16|16@1+ (1,-20000) [0|45535] "Kw"  PC
 SG_ M2P_Power_03 : 32|16@1+ (1,-20000) [0|45535] "Kw"  PC
 SG_ M2P_StepChrMode_03 : 48|2@1+ (1,0) [0|3] ""  PC
 SG_ M2P_BUS1_HVState_03 : 50|1@1+ (1,0) [0|1] ""  PC,SBMU
 SG_ M2P_BUS2_HVState_03 : 51|1@1+ (1,0) [0|1] ""  PC,SBMU
 SG_ M2P_BUS3_HVState_03 : 52|1@1+ (1,0) [0|1] ""  PC,SBMU
 SG_ M2P_BUS4_HVState_03 : 53|1@1+ (1,0) [0|1] ""  PC,SBMU
 SG_ M2P_BUS5_HVState_03 : 54|1@1+ (1,0) [0|1] ""  PC,SBMU
 SG_ M2P_BUS6_HVState_03 : 55|1@1+ (1,0) [0|1] ""  PC,SBMU
 SG_ M2P_BUS7_HVState_03 : 56|1@1+ (1,0) [0|1] ""  PC,SBMU
 SG_ M2P_BUS8_HVState_03 : 57|1@1+ (1,0) [0|1] ""  PC,SBMU
 SG_ M2P_BUS9_HVState_03 : 58|1@1+ (1,0) [0|1] ""  PC,SBMU
 SG_ M2P_BUS10_HVState_03 : 59|1@1+ (1,0) [0|1] ""  PC,SBMU
 SG_ M2P_BUS11_HVState_03 : 60|1@1+ (1,0) [0|1] ""  PC,SBMU
 SG_ M2P_BUS12_HVState_03 : 61|1@1+ (1,0) [0|1] ""  PC,SBMU

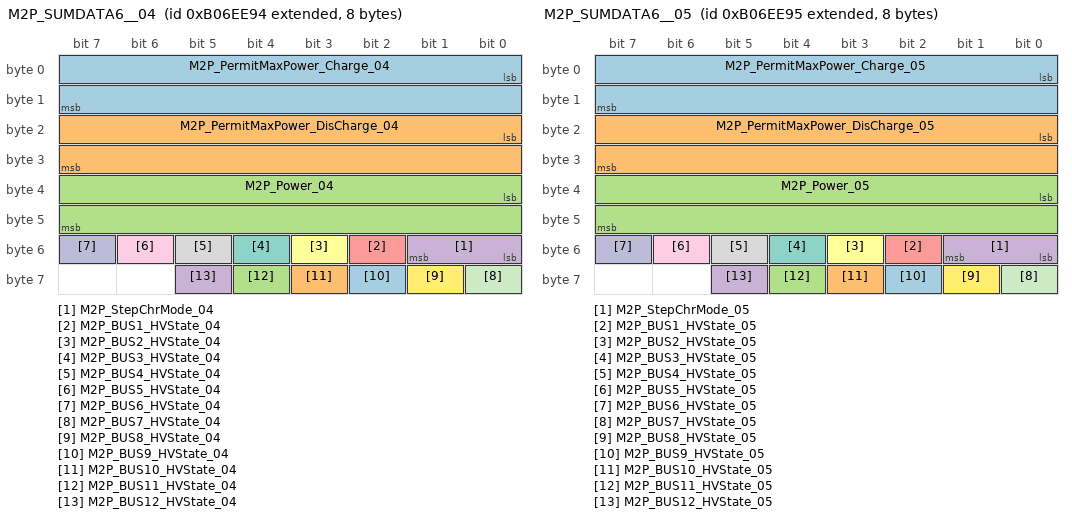
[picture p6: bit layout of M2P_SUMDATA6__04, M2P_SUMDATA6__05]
BO_ 2332487316 M2P_SUMDATA6__04: 8 MBMU
 SG_ M2P_PermitMaxPower_Charge_04 : 0|16@1+ (1,-20000) [0|45535] "Kw"  PC
 SG_ M2P_PermitMaxPower_DisCharge_04 : 16|16@1+ (1,-20000) [0|45535] "Kw"  PC
 SG_ M2P_Power_04 : 32|16@1+ (1,-20000) [0|45535] "Kw"  PC
 SG_ M2P_StepChrMode_04 : 48|2@1+ (1,0) [0|3] ""  PC
 SG_ M2P_BUS1_HVState_04 : 50|1@1+ (1,0) [0|1] ""  PC,SBMU
 SG_ M2P_BUS2_HVState_04 : 51|1@1+ (1,0) [0|1] ""  PC,SBMU
 SG_ M2P_BUS3_HVState_04 : 52|1@1+ (1,0) [0|1] ""  PC,SBMU
 SG_ M2P_BUS4_HVState_04 : 53|1@1+ (1,0) [0|1] ""  PC,SBMU
 SG_ M2P_BUS5_HVState_04 : 54|1@1+ (1,0) [0|1] ""  PC,SBMU
 SG_ M2P_BUS6_HVState_04 : 55|1@1+ (1,0) [0|1] ""  PC,SBMU
 SG_ M2P_BUS7_HVState_04 : 56|1@1+ (1,0) [0|1] ""  PC,SBMU
 SG_ M2P_BUS8_HVState_04 : 57|1@1+ (1,0) [0|1] ""  PC,SBMU
 SG_ M2P_BUS9_HVState_04 : 58|1@1+ (1,0) [0|1] ""  PC,SBMU
 SG_ M2P_BUS10_HVState_04 : 59|1@1+ (1,0) [0|1] ""  PC,SBMU
 SG_ M2P_BUS11_HVState_04 : 60|1@1+ (1,0) [0|1] ""  PC,SBMU
 SG_ M2P_BUS12_HVState_04 : 61|1@1+ (1,0) [0|1] ""  PC,SBMU

BO_ 2332487317 M2P_SUMDATA6__05: 8 MBMU
 SG_ M2P_PermitMaxPower_Charge_05 : 0|16@1+ (1,-20000) [0|45535] "Kw"  PC
 SG_ M2P_PermitMaxPower_DisCharge_05 : 16|16@1+ (1,-20000) [0|45535] "Kw"  PC
 SG_ M2P_Power_05 : 32|16@1+ (1,-20000) [0|45535] "Kw"  PC
 SG_ M2P_StepChrMode_05 : 48|2@1+ (1,0) [0|3] ""  PC
 SG_ M2P_BUS1_HVState_05 : 50|1@1+ (1,0) [0|1] ""  PC,SBMU
 SG_ M2P_BUS2_HVState_05 : 51|1@1+ (1,0) [0|1] ""  PC,SBMU
 SG_ M2P_BUS3_HVState_05 : 52|1@1+ (1,0) [0|1] ""  PC,SBMU
 SG_ M2P_BUS4_HVState_05 : 53|1@1+ (1,0) [0|1] ""  PC,SBMU
 SG_ M2P_BUS5_HVState_05 : 54|1@1+ (1,0) [0|1] ""  PC,SBMU
 SG_ M2P_BUS6_HVState_05 : 55|1@1+ (1,0) [0|1] ""  PC,SBMU
 SG_ M2P_BUS7_HVState_05 : 56|1@1+ (1,0) [0|1] ""  PC,SBMU
 SG_ M2P_BUS8_HVState_05 : 57|1@1+ (1,0) [0|1] ""  PC,SBMU
 SG_ M2P_BUS9_HVState_05 : 58|1@1+ (1,0) [0|1] ""  PC,SBMU
 SG_ M2P_BUS10_HVState_05 : 59|1@1+ (1,0) [0|1] ""  PC,SBMU
 SG_ M2P_BUS11_HVState_05 : 60|1@1+ (1,0) [0|1] ""  PC,SBMU
 SG_ M2P_BUS12_HVState_05 : 61|1@1+ (1,0) [0|1] ""  PC,SBMU

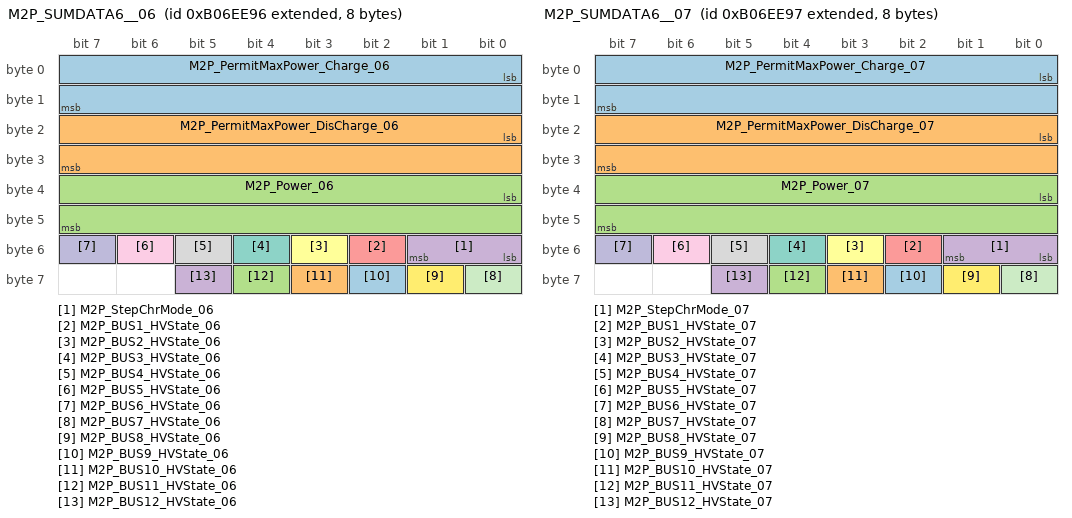
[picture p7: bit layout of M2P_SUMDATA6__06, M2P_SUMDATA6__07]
BO_ 2332487318 M2P_SUMDATA6__06: 8 MBMU
 SG_ M2P_PermitMaxPower_Charge_06 : 0|16@1+ (1,-20000) [0|45535] "Kw"  PC
 SG_ M2P_PermitMaxPower_DisCharge_06 : 16|16@1+ (1,-20000) [0|45535] "Kw"  PC
 SG_ M2P_Power_06 : 32|16@1+ (1,-20000) [0|45535] "Kw"  PC
 SG_ M2P_StepChrMode_06 : 48|2@1+ (1,0) [0|3] ""  PC
 SG_ M2P_BUS1_HVState_06 : 50|1@1+ (1,0) [0|1] ""  PC,SBMU
 SG_ M2P_BUS2_HVState_06 : 51|1@1+ (1,0) [0|1] ""  PC,SBMU
 SG_ M2P_BUS3_HVState_06 : 52|1@1+ (1,0) [0|1] ""  PC,SBMU
 SG_ M2P_BUS4_HVState_06 : 53|1@1+ (1,0) [0|1] ""  PC,SBMU
 SG_ M2P_BUS5_HVState_06 : 54|1@1+ (1,0) [0|1] ""  PC,SBMU
 SG_ M2P_BUS6_HVState_06 : 55|1@1+ (1,0) [0|1] ""  PC,SBMU
 SG_ M2P_BUS7_HVState_06 : 56|1@1+ (1,0) [0|1] ""  PC,SBMU
 SG_ M2P_BUS8_HVState_06 : 57|1@1+ (1,0) [0|1] ""  PC,SBMU
 SG_ M2P_BUS9_HVState_06 : 58|1@1+ (1,0) [0|1] ""  PC,SBMU
 SG_ M2P_BUS10_HVState_06 : 59|1@1+ (1,0) [0|1] ""  PC,SBMU
 SG_ M2P_BUS11_HVState_06 : 60|1@1+ (1,0) [0|1] ""  PC,SBMU
 SG_ M2P_BUS12_HVState_06 : 61|1@1+ (1,0) [0|1] ""  PC,SBMU

BO_ 2332487319 M2P_SUMDATA6__07: 8 MBMU
 SG_ M2P_PermitMaxPower_Charge_07 : 0|16@1+ (1,-20000) [0|45535] "Kw"  PC
 SG_ M2P_PermitMaxPower_DisCharge_07 : 16|16@1+ (1,-20000) [0|45535] "Kw"  PC
 SG_ M2P_Power_07 : 32|16@1+ (1,-20000) [0|45535] "Kw"  PC
 SG_ M2P_StepChrMode_07 : 48|2@1+ (1,0) [0|3] ""  PC
 SG_ M2P_BUS1_HVState_07 : 50|1@1+ (1,0) [0|1] ""  PC,SBMU
 SG_ M2P_BUS2_HVState_07 : 51|1@1+ (1,0) [0|1] ""  PC,SBMU
 SG_ M2P_BUS3_HVState_07 : 52|1@1+ (1,0) [0|1] ""  PC,SBMU
 SG_ M2P_BUS4_HVState_07 : 53|1@1+ (1,0) [0|1] ""  PC,SBMU
 SG_ M2P_BUS5_HVState_07 : 54|1@1+ (1,0) [0|1] ""  PC,SBMU
 SG_ M2P_BUS6_HVState_07 : 55|1@1+ (1,0) [0|1] ""  PC,SBMU
 SG_ M2P_BUS7_HVState_07 : 56|1@1+ (1,0) [0|1] ""  PC,SBMU
 SG_ M2P_BUS8_HVState_07 : 57|1@1+ (1,0) [0|1] ""  PC,SBMU
 SG_ M2P_BUS9_HVState_07 : 58|1@1+ (1,0) [0|1] ""  PC,SBMU
 SG_ M2P_BUS10_HVState_07 : 59|1@1+ (1,0) [0|1] ""  PC,SBMU
 SG_ M2P_BUS11_HVState_07 : 60|1@1+ (1,0) [0|1] ""  PC,SBMU
 SG_ M2P_BUS12_HVState_07 : 61|1@1+ (1,0) [0|1] ""  PC,SBMU

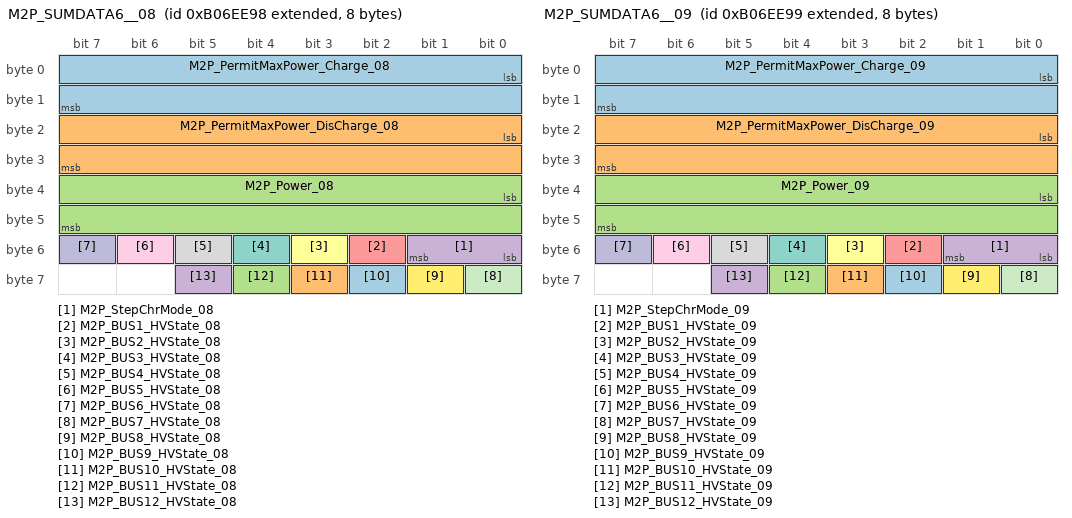
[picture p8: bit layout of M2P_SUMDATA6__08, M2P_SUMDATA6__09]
BO_ 2332487320 M2P_SUMDATA6__08: 8 MBMU
 SG_ M2P_PermitMaxPower_Charge_08 : 0|16@1+ (1,-20000) [0|45535] "Kw"  PC
 SG_ M2P_PermitMaxPower_DisCharge_08 : 16|16@1+ (1,-20000) [0|45535] "Kw"  PC
 SG_ M2P_Power_08 : 32|16@1+ (1,-20000) [0|45535] "Kw"  PC
 SG_ M2P_StepChrMode_08 : 48|2@1+ (1,0) [0|3] ""  PC
 SG_ M2P_BUS1_HVState_08 : 50|1@1+ (1,0) [0|1] ""  PC,SBMU
 SG_ M2P_BUS2_HVState_08 : 51|1@1+ (1,0) [0|1] ""  PC,SBMU
 SG_ M2P_BUS3_HVState_08 : 52|1@1+ (1,0) [0|1] ""  PC,SBMU
 SG_ M2P_BUS4_HVState_08 : 53|1@1+ (1,0) [0|1] ""  PC,SBMU
 SG_ M2P_BUS5_HVState_08 : 54|1@1+ (1,0) [0|1] ""  PC,SBMU
 SG_ M2P_BUS6_HVState_08 : 55|1@1+ (1,0) [0|1] ""  PC,SBMU
 SG_ M2P_BUS7_HVState_08 : 56|1@1+ (1,0) [0|1] ""  PC,SBMU
 SG_ M2P_BUS8_HVState_08 : 57|1@1+ (1,0) [0|1] ""  PC,SBMU
 SG_ M2P_BUS9_HVState_08 : 58|1@1+ (1,0) [0|1] ""  PC,SBMU
 SG_ M2P_BUS10_HVState_08 : 59|1@1+ (1,0) [0|1] ""  PC,SBMU
 SG_ M2P_BUS11_HVState_08 : 60|1@1+ (1,0) [0|1] ""  PC,SBMU
 SG_ M2P_BUS12_HVState_08 : 61|1@1+ (1,0) [0|1] ""  PC,SBMU

BO_ 2332487321 M2P_SUMDATA6__09: 8 MBMU
 SG_ M2P_PermitMaxPower_Charge_09 : 0|16@1+ (1,-20000) [0|45535] "Kw"  PC
 SG_ M2P_PermitMaxPower_DisCharge_09 : 16|16@1+ (1,-20000) [0|45535] "Kw"  PC
 SG_ M2P_Power_09 : 32|16@1+ (1,-20000) [0|45535] "Kw"  PC
 SG_ M2P_StepChrMode_09 : 48|2@1+ (1,0) [0|3] ""  PC
 SG_ M2P_BUS1_HVState_09 : 50|1@1+ (1,0) [0|1] ""  PC,SBMU
 SG_ M2P_BUS2_HVState_09 : 51|1@1+ (1,0) [0|1] ""  PC,SBMU
 SG_ M2P_BUS3_HVState_09 : 52|1@1+ (1,0) [0|1] ""  PC,SBMU
 SG_ M2P_BUS4_HVState_09 : 53|1@1+ (1,0) [0|1] ""  PC,SBMU
 SG_ M2P_BUS5_HVState_09 : 54|1@1+ (1,0) [0|1] ""  PC,SBMU
 SG_ M2P_BUS6_HVState_09 : 55|1@1+ (1,0) [0|1] ""  PC,SBMU
 SG_ M2P_BUS7_HVState_09 : 56|1@1+ (1,0) [0|1] ""  PC,SBMU
 SG_ M2P_BUS8_HVState_09 : 57|1@1+ (1,0) [0|1] ""  PC,SBMU
 SG_ M2P_BUS9_HVState_09 : 58|1@1+ (1,0) [0|1] ""  PC,SBMU
 SG_ M2P_BUS10_HVState_09 : 59|1@1+ (1,0) [0|1] ""  PC,SBMU
 SG_ M2P_BUS11_HVState_09 : 60|1@1+ (1,0) [0|1] ""  PC,SBMU
 SG_ M2P_BUS12_HVState_09 : 61|1@1+ (1,0) [0|1] ""  PC,SBMU

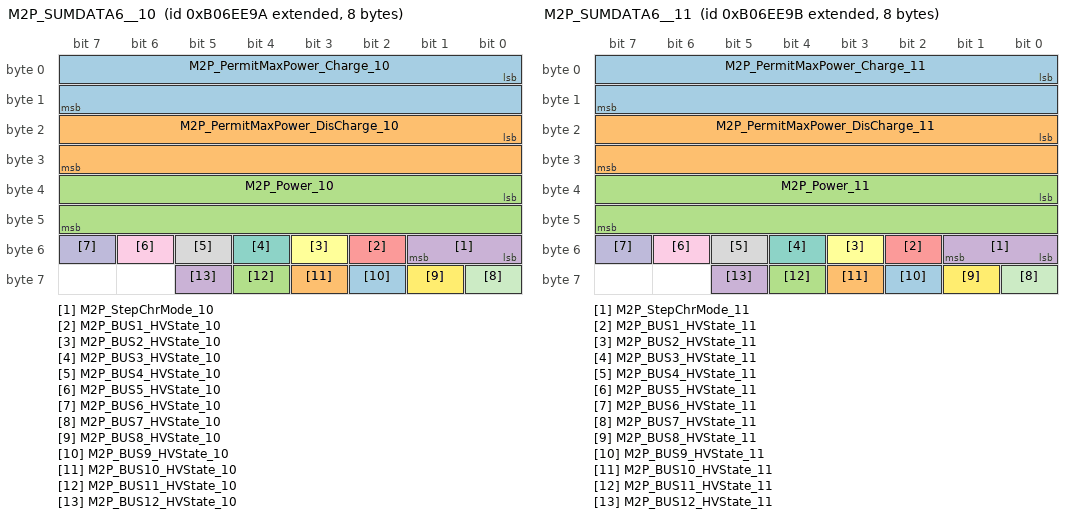
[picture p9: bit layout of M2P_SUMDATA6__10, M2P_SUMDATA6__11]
BO_ 2332487322 M2P_SUMDATA6__10: 8 MBMU
 SG_ M2P_PermitMaxPower_Charge_10 : 0|16@1+ (1,-20000) [0|45535] "Kw"  PC
 SG_ M2P_PermitMaxPower_DisCharge_10 : 16|16@1+ (1,-20000) [0|45535] "Kw"  PC
 SG_ M2P_Power_10 : 32|16@1+ (1,-20000) [0|45535] "Kw"  PC
 SG_ M2P_StepChrMode_10 : 48|2@1+ (1,0) [0|3] ""  PC
 SG_ M2P_BUS1_HVState_10 : 50|1@1+ (1,0) [0|1] ""  PC,SBMU
 SG_ M2P_BUS2_HVState_10 : 51|1@1+ (1,0) [0|1] ""  PC,SBMU
 SG_ M2P_BUS3_HVState_10 : 52|1@1+ (1,0) [0|1] ""  PC,SBMU
 SG_ M2P_BUS4_HVState_10 : 53|1@1+ (1,0) [0|1] ""  PC,SBMU
 SG_ M2P_BUS5_HVState_10 : 54|1@1+ (1,0) [0|1] ""  PC,SBMU
 SG_ M2P_BUS6_HVState_10 : 55|1@1+ (1,0) [0|1] ""  PC,SBMU
 SG_ M2P_BUS7_HVState_10 : 56|1@1+ (1,0) [0|1] ""  PC,SBMU
 SG_ M2P_BUS8_HVState_10 : 57|1@1+ (1,0) [0|1] ""  PC,SBMU
 SG_ M2P_BUS9_HVState_10 : 58|1@1+ (1,0) [0|1] ""  PC,SBMU
 SG_ M2P_BUS10_HVState_10 : 59|1@1+ (1,0) [0|1] ""  PC,SBMU
 SG_ M2P_BUS11_HVState_10 : 60|1@1+ (1,0) [0|1] ""  PC,SBMU
 SG_ M2P_BUS12_HVState_10 : 61|1@1+ (1,0) [0|1] ""  PC,SBMU

BO_ 2332487323 M2P_SUMDATA6__11: 8 MBMU
 SG_ M2P_PermitMaxPower_Charge_11 : 0|16@1+ (1,-20000) [0|45535] "Kw"  PC
 SG_ M2P_PermitMaxPower_DisCharge_11 : 16|16@1+ (1,-20000) [0|45535] "Kw"  PC
 SG_ M2P_Power_11 : 32|16@1+ (1,-20000) [0|45535] "Kw"  PC
 SG_ M2P_StepChrMode_11 : 48|2@1+ (1,0) [0|3] ""  PC
 SG_ M2P_BUS1_HVState_11 : 50|1@1+ (1,0) [0|1] ""  PC,SBMU
 SG_ M2P_BUS2_HVState_11 : 51|1@1+ (1,0) [0|1] ""  PC,SBMU
 SG_ M2P_BUS3_HVState_11 : 52|1@1+ (1,0) [0|1] ""  PC,SBMU
 SG_ M2P_BUS4_HVState_11 : 53|1@1+ (1,0) [0|1] ""  PC,SBMU
 SG_ M2P_BUS5_HVState_11 : 54|1@1+ (1,0) [0|1] ""  PC,SBMU
 SG_ M2P_BUS6_HVState_11 : 55|1@1+ (1,0) [0|1] ""  PC,SBMU
 SG_ M2P_BUS7_HVState_11 : 56|1@1+ (1,0) [0|1] ""  PC,SBMU
 SG_ M2P_BUS8_HVState_11 : 57|1@1+ (1,0) [0|1] ""  PC,SBMU
 SG_ M2P_BUS9_HVState_11 : 58|1@1+ (1,0) [0|1] ""  PC,SBMU
 SG_ M2P_BUS10_HVState_11 : 59|1@1+ (1,0) [0|1] ""  PC,SBMU
 SG_ M2P_BUS11_HVState_11 : 60|1@1+ (1,0) [0|1] ""  PC,SBMU
 SG_ M2P_BUS12_HVState_11 : 61|1@1+ (1,0) [0|1] ""  PC,SBMU

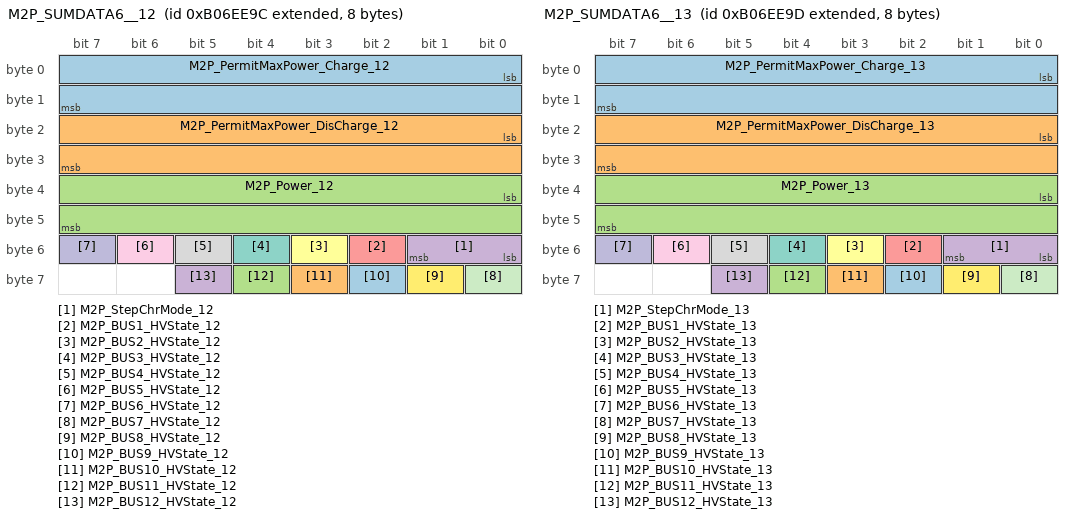
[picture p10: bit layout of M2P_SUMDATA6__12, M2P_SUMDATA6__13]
BO_ 2332487324 M2P_SUMDATA6__12: 8 MBMU
 SG_ M2P_PermitMaxPower_Charge_12 : 0|16@1+ (1,-20000) [0|45535] "Kw"  PC
 SG_ M2P_PermitMaxPower_DisCharge_12 : 16|16@1+ (1,-20000) [0|45535] "Kw"  PC
 SG_ M2P_Power_12 : 32|16@1+ (1,-20000) [0|45535] "Kw"  PC
 SG_ M2P_StepChrMode_12 : 48|2@1+ (1,0) [0|3] ""  PC
 SG_ M2P_BUS1_HVState_12 : 50|1@1+ (1,0) [0|1] ""  PC,SBMU
 SG_ M2P_BUS2_HVState_12 : 51|1@1+ (1,0) [0|1] ""  PC,SBMU
 SG_ M2P_BUS3_HVState_12 : 52|1@1+ (1,0) [0|1] ""  PC,SBMU
 SG_ M2P_BUS4_HVState_12 : 53|1@1+ (1,0) [0|1] ""  PC,SBMU
 SG_ M2P_BUS5_HVState_12 : 54|1@1+ (1,0) [0|1] ""  PC,SBMU
 SG_ M2P_BUS6_HVState_12 : 55|1@1+ (1,0) [0|1] ""  PC,SBMU
 SG_ M2P_BUS7_HVState_12 : 56|1@1+ (1,0) [0|1] ""  PC,SBMU
 SG_ M2P_BUS8_HVState_12 : 57|1@1+ (1,0) [0|1] ""  PC,SBMU
 SG_ M2P_BUS9_HVState_12 : 58|1@1+ (1,0) [0|1] ""  PC,SBMU
 SG_ M2P_BUS10_HVState_12 : 59|1@1+ (1,0) [0|1] ""  PC,SBMU
 SG_ M2P_BUS11_HVState_12 : 60|1@1+ (1,0) [0|1] ""  PC,SBMU
 SG_ M2P_BUS12_HVState_12 : 61|1@1+ (1,0) [0|1] ""  PC,SBMU

BO_ 2332487325 M2P_SUMDATA6__13: 8 MBMU
 SG_ M2P_PermitMaxPower_Charge_13 : 0|16@1+ (1,-20000) [0|45535] "Kw"  PC
 SG_ M2P_PermitMaxPower_DisCharge_13 : 16|16@1+ (1,-20000) [0|45535] "Kw"  PC
 SG_ M2P_Power_13 : 32|16@1+ (1,-20000) [0|45535] "Kw"  PC
 SG_ M2P_StepChrMode_13 : 48|2@1+ (1,0) [0|3] ""  PC
 SG_ M2P_BUS1_HVState_13 : 50|1@1+ (1,0) [0|1] ""  PC,SBMU
 SG_ M2P_BUS2_HVState_13 : 51|1@1+ (1,0) [0|1] ""  PC,SBMU
 SG_ M2P_BUS3_HVState_13 : 52|1@1+ (1,0) [0|1] ""  PC,SBMU
 SG_ M2P_BUS4_HVState_13 : 53|1@1+ (1,0) [0|1] ""  PC,SBMU
 SG_ M2P_BUS5_HVState_13 : 54|1@1+ (1,0) [0|1] ""  PC,SBMU
 SG_ M2P_BUS6_HVState_13 : 55|1@1+ (1,0) [0|1] ""  PC,SBMU
 SG_ M2P_BUS7_HVState_13 : 56|1@1+ (1,0) [0|1] ""  PC,SBMU
 SG_ M2P_BUS8_HVState_13 : 57|1@1+ (1,0) [0|1] ""  PC,SBMU
 SG_ M2P_BUS9_HVState_13 : 58|1@1+ (1,0) [0|1] ""  PC,SBMU
 SG_ M2P_BUS10_HVState_13 : 59|1@1+ (1,0) [0|1] ""  PC,SBMU
 SG_ M2P_BUS11_HVState_13 : 60|1@1+ (1,0) [0|1] ""  PC,SBMU
 SG_ M2P_BUS12_HVState_13 : 61|1@1+ (1,0) [0|1] ""  PC,SBMU

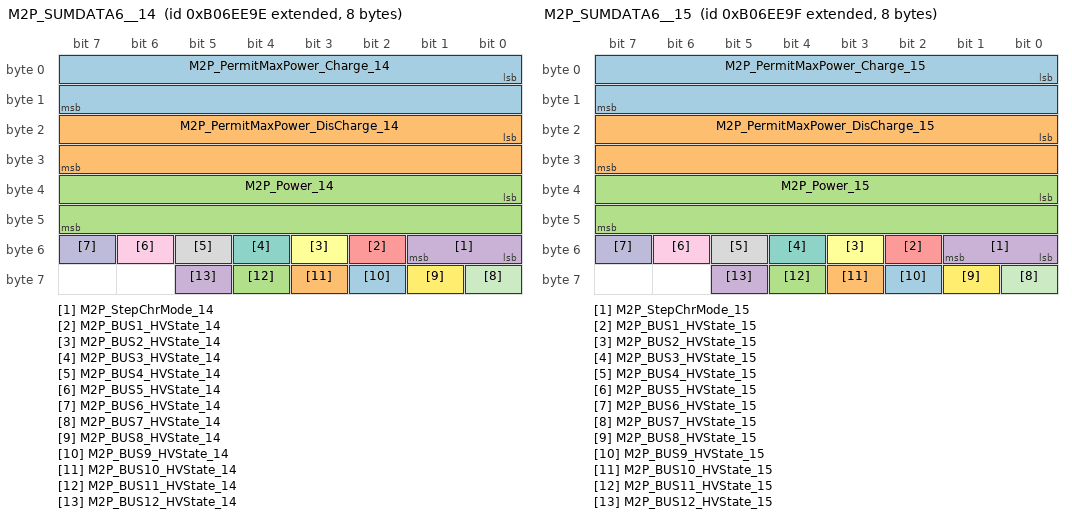
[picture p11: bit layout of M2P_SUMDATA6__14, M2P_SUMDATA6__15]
BO_ 2332487326 M2P_SUMDATA6__14: 8 MBMU
 SG_ M2P_PermitMaxPower_Charge_14 : 0|16@1+ (1,-20000) [0|45535] "Kw"  PC
 SG_ M2P_PermitMaxPower_DisCharge_14 : 16|16@1+ (1,-20000) [0|45535] "Kw"  PC
 SG_ M2P_Power_14 : 32|16@1+ (1,-20000) [0|45535] "Kw"  PC
 SG_ M2P_StepChrMode_14 : 48|2@1+ (1,0) [0|3] ""  PC
 SG_ M2P_BUS1_HVState_14 : 50|1@1+ (1,0) [0|1] ""  PC,SBMU
 SG_ M2P_BUS2_HVState_14 : 51|1@1+ (1,0) [0|1] ""  PC,SBMU
 SG_ M2P_BUS3_HVState_14 : 52|1@1+ (1,0) [0|1] ""  PC,SBMU
 SG_ M2P_BUS4_HVState_14 : 53|1@1+ (1,0) [0|1] ""  PC,SBMU
 SG_ M2P_BUS5_HVState_14 : 54|1@1+ (1,0) [0|1] ""  PC,SBMU
 SG_ M2P_BUS6_HVState_14 : 55|1@1+ (1,0) [0|1] ""  PC,SBMU
 SG_ M2P_BUS7_HVState_14 : 56|1@1+ (1,0) [0|1] ""  PC,SBMU
 SG_ M2P_BUS8_HVState_14 : 57|1@1+ (1,0) [0|1] ""  PC,SBMU
 SG_ M2P_BUS9_HVState_14 : 58|1@1+ (1,0) [0|1] ""  PC,SBMU
 SG_ M2P_BUS10_HVState_14 : 59|1@1+ (1,0) [0|1] ""  PC,SBMU
 SG_ M2P_BUS11_HVState_14 : 60|1@1+ (1,0) [0|1] ""  PC,SBMU
 SG_ M2P_BUS12_HVState_14 : 61|1@1+ (1,0) [0|1] ""  PC,SBMU

BO_ 2332487327 M2P_SUMDATA6__15: 8 MBMU
 SG_ M2P_PermitMaxPower_Charge_15 : 0|16@1+ (1,-20000) [0|45535] "Kw"  PC
 SG_ M2P_PermitMaxPower_DisCharge_15 : 16|16@1+ (1,-20000) [0|45535] "Kw"  PC
 SG_ M2P_Power_15 : 32|16@1+ (1,-20000) [0|45535] "Kw"  PC
 SG_ M2P_StepChrMode_15 : 48|2@1+ (1,0) [0|3] ""  PC
 SG_ M2P_BUS1_HVState_15 : 50|1@1+ (1,0) [0|1] ""  PC,SBMU
 SG_ M2P_BUS2_HVState_15 : 51|1@1+ (1,0) [0|1] ""  PC,SBMU
 SG_ M2P_BUS3_HVState_15 : 52|1@1+ (1,0) [0|1] ""  PC,SBMU
 SG_ M2P_BUS4_HVState_15 : 53|1@1+ (1,0) [0|1] ""  PC,SBMU
 SG_ M2P_BUS5_HVState_15 : 54|1@1+ (1,0) [0|1] ""  PC,SBMU
 SG_ M2P_BUS6_HVState_15 : 55|1@1+ (1,0) [0|1] ""  PC,SBMU
 SG_ M2P_BUS7_HVState_15 : 56|1@1+ (1,0) [0|1] ""  PC,SBMU
 SG_ M2P_BUS8_HVState_15 : 57|1@1+ (1,0) [0|1] ""  PC,SBMU
 SG_ M2P_BUS9_HVState_15 : 58|1@1+ (1,0) [0|1] ""  PC,SBMU
 SG_ M2P_BUS10_HVState_15 : 59|1@1+ (1,0) [0|1] ""  PC,SBMU
 SG_ M2P_BUS11_HVState_15 : 60|1@1+ (1,0) [0|1] ""  PC,SBMU
 SG_ M2P_BUS12_HVState_15 : 61|1@1+ (1,0) [0|1] ""  PC,SBMU

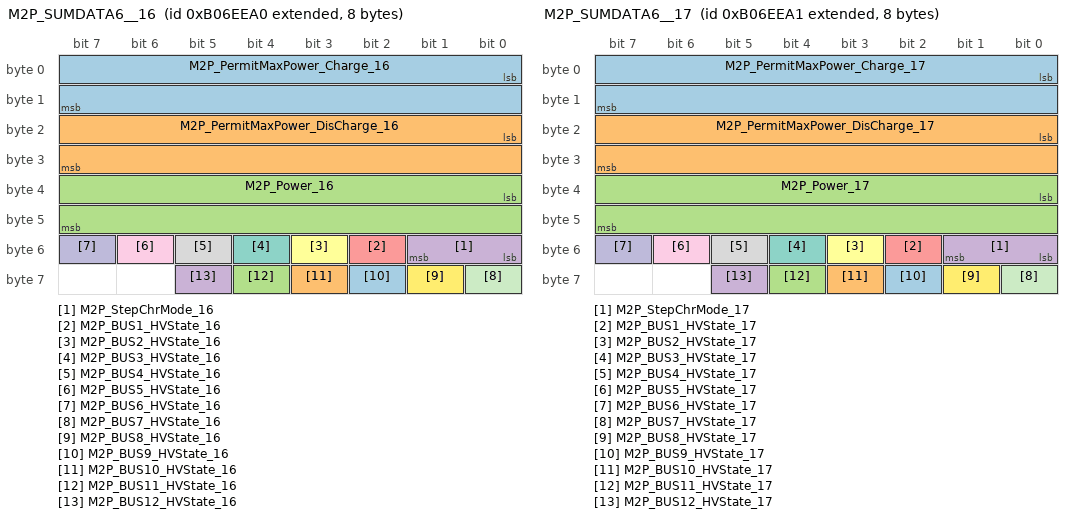
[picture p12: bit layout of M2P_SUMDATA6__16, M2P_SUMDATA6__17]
BO_ 2332487328 M2P_SUMDATA6__16: 8 MBMU
 SG_ M2P_PermitMaxPower_Charge_16 : 0|16@1+ (1,-20000) [0|45535] "Kw"  PC
 SG_ M2P_PermitMaxPower_DisCharge_16 : 16|16@1+ (1,-20000) [0|45535] "Kw"  PC
 SG_ M2P_Power_16 : 32|16@1+ (1,-20000) [0|45535] "Kw"  PC
 SG_ M2P_StepChrMode_16 : 48|2@1+ (1,0) [0|3] ""  PC
 SG_ M2P_BUS1_HVState_16 : 50|1@1+ (1,0) [0|1] ""  PC,SBMU
 SG_ M2P_BUS2_HVState_16 : 51|1@1+ (1,0) [0|1] ""  PC,SBMU
 SG_ M2P_BUS3_HVState_16 : 52|1@1+ (1,0) [0|1] ""  PC,SBMU
 SG_ M2P_BUS4_HVState_16 : 53|1@1+ (1,0) [0|1] ""  PC,SBMU
 SG_ M2P_BUS5_HVState_16 : 54|1@1+ (1,0) [0|1] ""  PC,SBMU
 SG_ M2P_BUS6_HVState_16 : 55|1@1+ (1,0) [0|1] ""  PC,SBMU
 SG_ M2P_BUS7_HVState_16 : 56|1@1+ (1,0) [0|1] ""  PC,SBMU
 SG_ M2P_BUS8_HVState_16 : 57|1@1+ (1,0) [0|1] ""  PC,SBMU
 SG_ M2P_BUS9_HVState_16 : 58|1@1+ (1,0) [0|1] ""  PC,SBMU
 SG_ M2P_BUS10_HVState_16 : 59|1@1+ (1,0) [0|1] ""  PC,SBMU
 SG_ M2P_BUS11_HVState_16 : 60|1@1+ (1,0) [0|1] ""  PC,SBMU
 SG_ M2P_BUS12_HVState_16 : 61|1@1+ (1,0) [0|1] ""  PC,SBMU

BO_ 2332487329 M2P_SUMDATA6__17: 8 MBMU
 SG_ M2P_PermitMaxPower_Charge_17 : 0|16@1+ (1,-20000) [0|45535] "Kw"  PC
 SG_ M2P_PermitMaxPower_DisCharge_17 : 16|16@1+ (1,-20000) [0|45535] "Kw"  PC
 SG_ M2P_Power_17 : 32|16@1+ (1,-20000) [0|45535] "Kw"  PC
 SG_ M2P_StepChrMode_17 : 48|2@1+ (1,0) [0|3] ""  PC
 SG_ M2P_BUS1_HVState_17 : 50|1@1+ (1,0) [0|1] ""  PC,SBMU
 SG_ M2P_BUS2_HVState_17 : 51|1@1+ (1,0) [0|1] ""  PC,SBMU
 SG_ M2P_BUS3_HVState_17 : 52|1@1+ (1,0) [0|1] ""  PC,SBMU
 SG_ M2P_BUS4_HVState_17 : 53|1@1+ (1,0) [0|1] ""  PC,SBMU
 SG_ M2P_BUS5_HVState_17 : 54|1@1+ (1,0) [0|1] ""  PC,SBMU
 SG_ M2P_BUS6_HVState_17 : 55|1@1+ (1,0) [0|1] ""  PC,SBMU
 SG_ M2P_BUS7_HVState_17 : 56|1@1+ (1,0) [0|1] ""  PC,SBMU
 SG_ M2P_BUS8_HVState_17 : 57|1@1+ (1,0) [0|1] ""  PC,SBMU
 SG_ M2P_BUS9_HVState_17 : 58|1@1+ (1,0) [0|1] ""  PC,SBMU
 SG_ M2P_BUS10_HVState_17 : 59|1@1+ (1,0) [0|1] ""  PC,SBMU
 SG_ M2P_BUS11_HVState_17 : 60|1@1+ (1,0) [0|1] ""  PC,SBMU
 SG_ M2P_BUS12_HVState_17 : 61|1@1+ (1,0) [0|1] ""  PC,SBMU

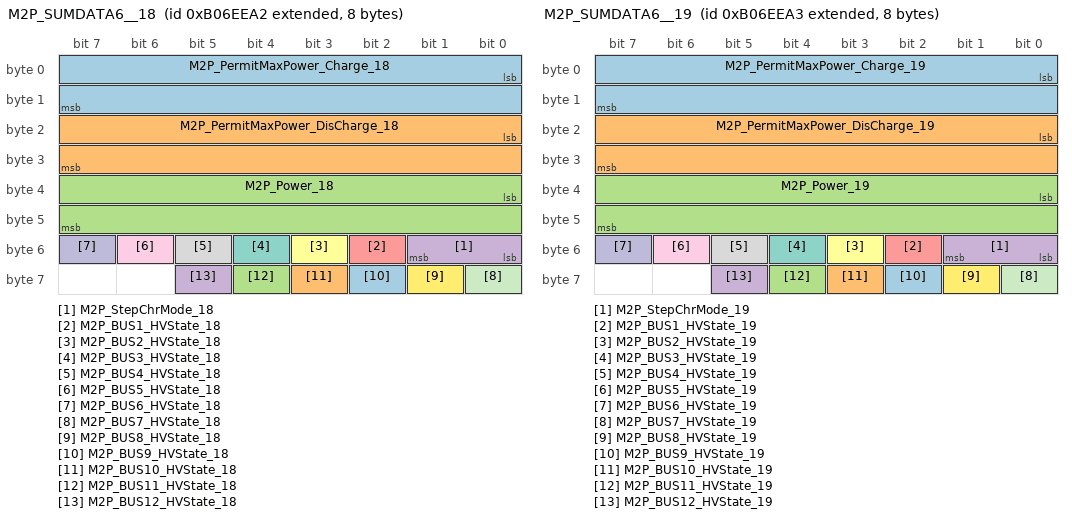
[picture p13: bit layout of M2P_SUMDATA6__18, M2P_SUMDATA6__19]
BO_ 2332487330 M2P_SUMDATA6__18: 8 MBMU
 SG_ M2P_PermitMaxPower_Charge_18 : 0|16@1+ (1,-20000) [0|45535] "Kw"  PC
 SG_ M2P_PermitMaxPower_DisCharge_18 : 16|16@1+ (1,-20000) [0|45535] "Kw"  PC
 SG_ M2P_Power_18 : 32|16@1+ (1,-20000) [0|45535] "Kw"  PC
 SG_ M2P_StepChrMode_18 : 48|2@1+ (1,0) [0|3] ""  PC
 SG_ M2P_BUS1_HVState_18 : 50|1@1+ (1,0) [0|1] ""  PC,SBMU
 SG_ M2P_BUS2_HVState_18 : 51|1@1+ (1,0) [0|1] ""  PC,SBMU
 SG_ M2P_BUS3_HVState_18 : 52|1@1+ (1,0) [0|1] ""  PC,SBMU
 SG_ M2P_BUS4_HVState_18 : 53|1@1+ (1,0) [0|1] ""  PC,SBMU
 SG_ M2P_BUS5_HVState_18 : 54|1@1+ (1,0) [0|1] ""  PC,SBMU
 SG_ M2P_BUS6_HVState_18 : 55|1@1+ (1,0) [0|1] ""  PC,SBMU
 SG_ M2P_BUS7_HVState_18 : 56|1@1+ (1,0) [0|1] ""  PC,SBMU
 SG_ M2P_BUS8_HVState_18 : 57|1@1+ (1,0) [0|1] ""  PC,SBMU
 SG_ M2P_BUS9_HVState_18 : 58|1@1+ (1,0) [0|1] ""  PC,SBMU
 SG_ M2P_BUS10_HVState_18 : 59|1@1+ (1,0) [0|1] ""  PC,SBMU
 SG_ M2P_BUS11_HVState_18 : 60|1@1+ (1,0) [0|1] ""  PC,SBMU
 SG_ M2P_BUS12_HVState_18 : 61|1@1+ (1,0) [0|1] ""  PC,SBMU

BO_ 2332487331 M2P_SUMDATA6__19: 8 MBMU
 SG_ M2P_PermitMaxPower_Charge_19 : 0|16@1+ (1,-20000) [0|45535] "Kw"  PC
 SG_ M2P_PermitMaxPower_DisCharge_19 : 16|16@1+ (1,-20000) [0|45535] "Kw"  PC
 SG_ M2P_Power_19 : 32|16@1+ (1,-20000) [0|45535] "Kw"  PC
 SG_ M2P_StepChrMode_19 : 48|2@1+ (1,0) [0|3] ""  PC
 SG_ M2P_BUS1_HVState_19 : 50|1@1+ (1,0) [0|1] ""  PC,SBMU
 SG_ M2P_BUS2_HVState_19 : 51|1@1+ (1,0) [0|1] ""  PC,SBMU
 SG_ M2P_BUS3_HVState_19 : 52|1@1+ (1,0) [0|1] ""  PC,SBMU
 SG_ M2P_BUS4_HVState_19 : 53|1@1+ (1,0) [0|1] ""  PC,SBMU
 SG_ M2P_BUS5_HVState_19 : 54|1@1+ (1,0) [0|1] ""  PC,SBMU
 SG_ M2P_BUS6_HVState_19 : 55|1@1+ (1,0) [0|1] ""  PC,SBMU
 SG_ M2P_BUS7_HVState_19 : 56|1@1+ (1,0) [0|1] ""  PC,SBMU
 SG_ M2P_BUS8_HVState_19 : 57|1@1+ (1,0) [0|1] ""  PC,SBMU
 SG_ M2P_BUS9_HVState_19 : 58|1@1+ (1,0) [0|1] ""  PC,SBMU
 SG_ M2P_BUS10_HVState_19 : 59|1@1+ (1,0) [0|1] ""  PC,SBMU
 SG_ M2P_BUS11_HVState_19 : 60|1@1+ (1,0) [0|1] ""  PC,SBMU
 SG_ M2P_BUS12_HVState_19 : 61|1@1+ (1,0) [0|1] ""  PC,SBMU

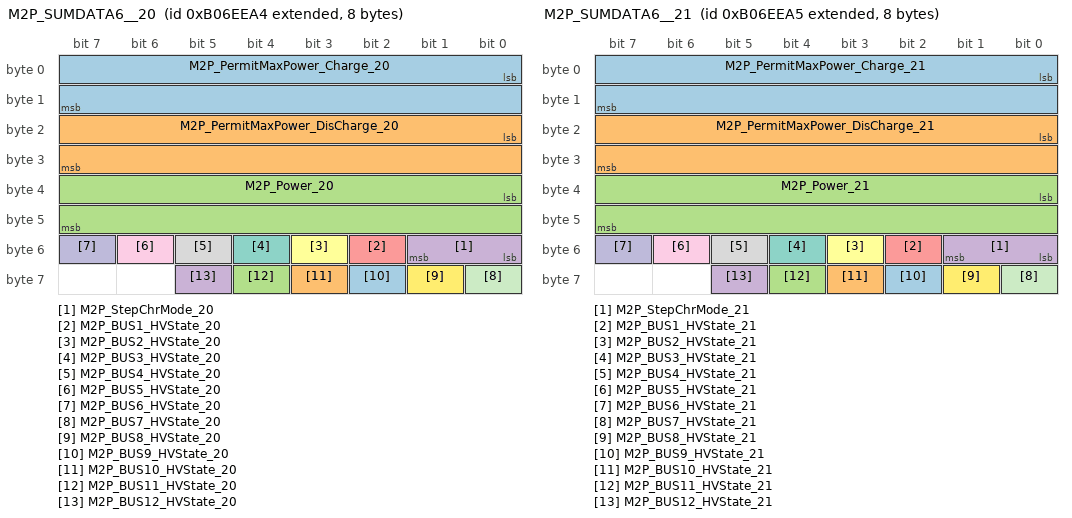
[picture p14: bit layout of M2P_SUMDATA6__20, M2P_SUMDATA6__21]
BO_ 2332487332 M2P_SUMDATA6__20: 8 MBMU
 SG_ M2P_PermitMaxPower_Charge_20 : 0|16@1+ (1,-20000) [0|45535] "Kw"  PC
 SG_ M2P_PermitMaxPower_DisCharge_20 : 16|16@1+ (1,-20000) [0|45535] "Kw"  PC
 SG_ M2P_Power_20 : 32|16@1+ (1,-20000) [0|45535] "Kw"  PC
 SG_ M2P_StepChrMode_20 : 48|2@1+ (1,0) [0|3] ""  PC
 SG_ M2P_BUS1_HVState_20 : 50|1@1+ (1,0) [0|1] ""  PC,SBMU
 SG_ M2P_BUS2_HVState_20 : 51|1@1+ (1,0) [0|1] ""  PC,SBMU
 SG_ M2P_BUS3_HVState_20 : 52|1@1+ (1,0) [0|1] ""  PC,SBMU
 SG_ M2P_BUS4_HVState_20 : 53|1@1+ (1,0) [0|1] ""  PC,SBMU
 SG_ M2P_BUS5_HVState_20 : 54|1@1+ (1,0) [0|1] ""  PC,SBMU
 SG_ M2P_BUS6_HVState_20 : 55|1@1+ (1,0) [0|1] ""  PC,SBMU
 SG_ M2P_BUS7_HVState_20 : 56|1@1+ (1,0) [0|1] ""  PC,SBMU
 SG_ M2P_BUS8_HVState_20 : 57|1@1+ (1,0) [0|1] ""  PC,SBMU
 SG_ M2P_BUS9_HVState_20 : 58|1@1+ (1,0) [0|1] ""  PC,SBMU
 SG_ M2P_BUS10_HVState_20 : 59|1@1+ (1,0) [0|1] ""  PC,SBMU
 SG_ M2P_BUS11_HVState_20 : 60|1@1+ (1,0) [0|1] ""  PC,SBMU
 SG_ M2P_BUS12_HVState_20 : 61|1@1+ (1,0) [0|1] ""  PC,SBMU

BO_ 2332487333 M2P_SUMDATA6__21: 8 MBMU
 SG_ M2P_PermitMaxPower_Charge_21 : 0|16@1+ (1,-20000) [0|45535] "Kw"  PC
 SG_ M2P_PermitMaxPower_DisCharge_21 : 16|16@1+ (1,-20000) [0|45535] "Kw"  PC
 SG_ M2P_Power_21 : 32|16@1+ (1,-20000) [0|45535] "Kw"  PC
 SG_ M2P_StepChrMode_21 : 48|2@1+ (1,0) [0|3] ""  PC
 SG_ M2P_BUS1_HVState_21 : 50|1@1+ (1,0) [0|1] ""  PC,SBMU
 SG_ M2P_BUS2_HVState_21 : 51|1@1+ (1,0) [0|1] ""  PC,SBMU
 SG_ M2P_BUS3_HVState_21 : 52|1@1+ (1,0) [0|1] ""  PC,SBMU
 SG_ M2P_BUS4_HVState_21 : 53|1@1+ (1,0) [0|1] ""  PC,SBMU
 SG_ M2P_BUS5_HVState_21 : 54|1@1+ (1,0) [0|1] ""  PC,SBMU
 SG_ M2P_BUS6_HVState_21 : 55|1@1+ (1,0) [0|1] ""  PC,SBMU
 SG_ M2P_BUS7_HVState_21 : 56|1@1+ (1,0) [0|1] ""  PC,SBMU
 SG_ M2P_BUS8_HVState_21 : 57|1@1+ (1,0) [0|1] ""  PC,SBMU
 SG_ M2P_BUS9_HVState_21 : 58|1@1+ (1,0) [0|1] ""  PC,SBMU
 SG_ M2P_BUS10_HVState_21 : 59|1@1+ (1,0) [0|1] ""  PC,SBMU
 SG_ M2P_BUS11_HVState_21 : 60|1@1+ (1,0) [0|1] ""  PC,SBMU
 SG_ M2P_BUS12_HVState_21 : 61|1@1+ (1,0) [0|1] ""  PC,SBMU

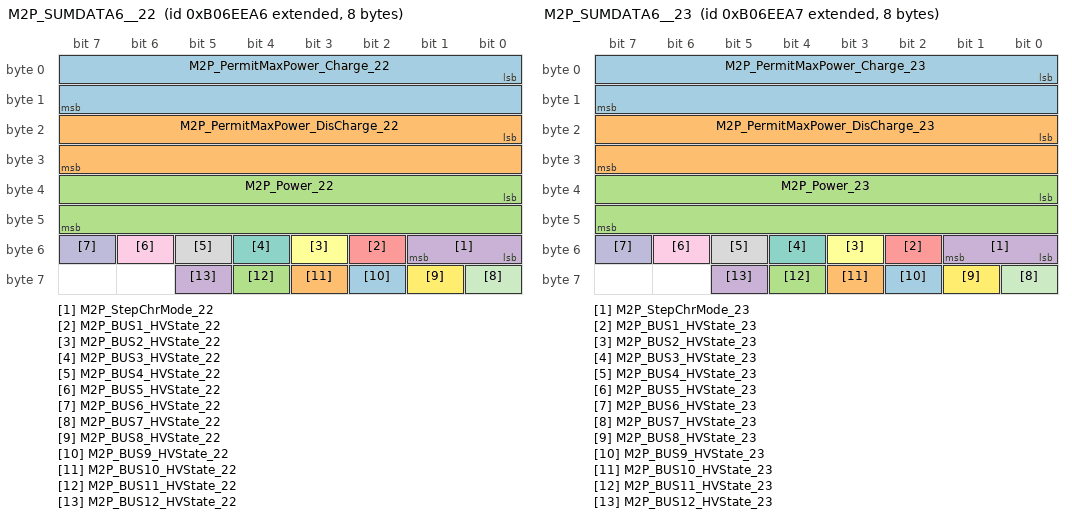
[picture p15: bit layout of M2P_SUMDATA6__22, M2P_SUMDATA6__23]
BO_ 2332487334 M2P_SUMDATA6__22: 8 MBMU
 SG_ M2P_PermitMaxPower_Charge_22 : 0|16@1+ (1,-20000) [0|45535] "Kw"  PC
 SG_ M2P_PermitMaxPower_DisCharge_22 : 16|16@1+ (1,-20000) [0|45535] "Kw"  PC
 SG_ M2P_Power_22 : 32|16@1+ (1,-20000) [0|45535] "Kw"  PC
 SG_ M2P_StepChrMode_22 : 48|2@1+ (1,0) [0|3] ""  PC
 SG_ M2P_BUS1_HVState_22 : 50|1@1+ (1,0) [0|1] ""  PC,SBMU
 SG_ M2P_BUS2_HVState_22 : 51|1@1+ (1,0) [0|1] ""  PC,SBMU
 SG_ M2P_BUS3_HVState_22 : 52|1@1+ (1,0) [0|1] ""  PC,SBMU
 SG_ M2P_BUS4_HVState_22 : 53|1@1+ (1,0) [0|1] ""  PC,SBMU
 SG_ M2P_BUS5_HVState_22 : 54|1@1+ (1,0) [0|1] ""  PC,SBMU
 SG_ M2P_BUS6_HVState_22 : 55|1@1+ (1,0) [0|1] ""  PC,SBMU
 SG_ M2P_BUS7_HVState_22 : 56|1@1+ (1,0) [0|1] ""  PC,SBMU
 SG_ M2P_BUS8_HVState_22 : 57|1@1+ (1,0) [0|1] ""  PC,SBMU
 SG_ M2P_BUS9_HVState_22 : 58|1@1+ (1,0) [0|1] ""  PC,SBMU
 SG_ M2P_BUS10_HVState_22 : 59|1@1+ (1,0) [0|1] ""  PC,SBMU
 SG_ M2P_BUS11_HVState_22 : 60|1@1+ (1,0) [0|1] ""  PC,SBMU
 SG_ M2P_BUS12_HVState_22 : 61|1@1+ (1,0) [0|1] ""  PC,SBMU

BO_ 2332487335 M2P_SUMDATA6__23: 8 MBMU
 SG_ M2P_PermitMaxPower_Charge_23 : 0|16@1+ (1,-20000) [0|45535] "Kw"  PC
 SG_ M2P_PermitMaxPower_DisCharge_23 : 16|16@1+ (1,-20000) [0|45535] "Kw"  PC
 SG_ M2P_Power_23 : 32|16@1+ (1,-20000) [0|45535] "Kw"  PC
 SG_ M2P_StepChrMode_23 : 48|2@1+ (1,0) [0|3] ""  PC
 SG_ M2P_BUS1_HVState_23 : 50|1@1+ (1,0) [0|1] ""  PC,SBMU
 SG_ M2P_BUS2_HVState_23 : 51|1@1+ (1,0) [0|1] ""  PC,SBMU
 SG_ M2P_BUS3_HVState_23 : 52|1@1+ (1,0) [0|1] ""  PC,SBMU
 SG_ M2P_BUS4_HVState_23 : 53|1@1+ (1,0) [0|1] ""  PC,SBMU
 SG_ M2P_BUS5_HVState_23 : 54|1@1+ (1,0) [0|1] ""  PC,SBMU
 SG_ M2P_BUS6_HVState_23 : 55|1@1+ (1,0) [0|1] ""  PC,SBMU
 SG_ M2P_BUS7_HVState_23 : 56|1@1+ (1,0) [0|1] ""  PC,SBMU
 SG_ M2P_BUS8_HVState_23 : 57|1@1+ (1,0) [0|1] ""  PC,SBMU
 SG_ M2P_BUS9_HVState_23 : 58|1@1+ (1,0) [0|1] ""  PC,SBMU
 SG_ M2P_BUS10_HVState_23 : 59|1@1+ (1,0) [0|1] ""  PC,SBMU
 SG_ M2P_BUS11_HVState_23 : 60|1@1+ (1,0) [0|1] ""  PC,SBMU
 SG_ M2P_BUS12_HVState_23 : 61|1@1+ (1,0) [0|1] ""  PC,SBMU

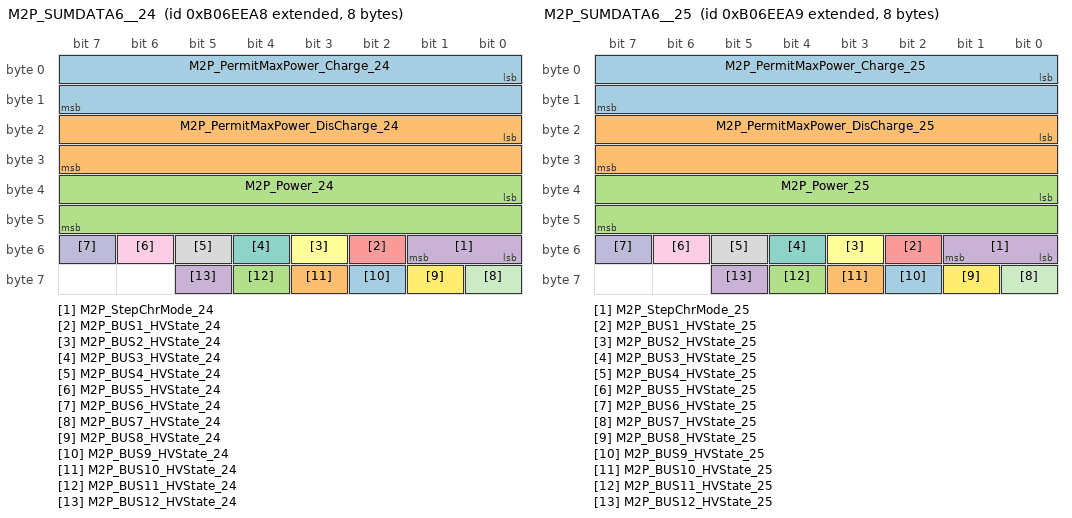
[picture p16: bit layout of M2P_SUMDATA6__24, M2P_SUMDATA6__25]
BO_ 2332487336 M2P_SUMDATA6__24: 8 MBMU
 SG_ M2P_PermitMaxPower_Charge_24 : 0|16@1+ (1,-20000) [0|45535] "Kw"  PC
 SG_ M2P_PermitMaxPower_DisCharge_24 : 16|16@1+ (1,-20000) [0|45535] "Kw"  PC
 SG_ M2P_Power_24 : 32|16@1+ (1,-20000) [0|45535] "Kw"  PC
 SG_ M2P_StepChrMode_24 : 48|2@1+ (1,0) [0|3] ""  PC
 SG_ M2P_BUS1_HVState_24 : 50|1@1+ (1,0) [0|1] ""  PC,SBMU
 SG_ M2P_BUS2_HVState_24 : 51|1@1+ (1,0) [0|1] ""  PC,SBMU
 SG_ M2P_BUS3_HVState_24 : 52|1@1+ (1,0) [0|1] ""  PC,SBMU
 SG_ M2P_BUS4_HVState_24 : 53|1@1+ (1,0) [0|1] ""  PC,SBMU
 SG_ M2P_BUS5_HVState_24 : 54|1@1+ (1,0) [0|1] ""  PC,SBMU
 SG_ M2P_BUS6_HVState_24 : 55|1@1+ (1,0) [0|1] ""  PC,SBMU
 SG_ M2P_BUS7_HVState_24 : 56|1@1+ (1,0) [0|1] ""  PC,SBMU
 SG_ M2P_BUS8_HVState_24 : 57|1@1+ (1,0) [0|1] ""  PC,SBMU
 SG_ M2P_BUS9_HVState_24 : 58|1@1+ (1,0) [0|1] ""  PC,SBMU
 SG_ M2P_BUS10_HVState_24 : 59|1@1+ (1,0) [0|1] ""  PC,SBMU
 SG_ M2P_BUS11_HVState_24 : 60|1@1+ (1,0) [0|1] ""  PC,SBMU
 SG_ M2P_BUS12_HVState_24 : 61|1@1+ (1,0) [0|1] ""  PC,SBMU

BO_ 2332487337 M2P_SUMDATA6__25: 8 MBMU
 SG_ M2P_PermitMaxPower_Charge_25 : 0|16@1+ (1,-20000) [0|45535] "Kw"  PC
 SG_ M2P_PermitMaxPower_DisCharge_25 : 16|16@1+ (1,-20000) [0|45535] "Kw"  PC
 SG_ M2P_Power_25 : 32|16@1+ (1,-20000) [0|45535] "Kw"  PC
 SG_ M2P_StepChrMode_25 : 48|2@1+ (1,0) [0|3] ""  PC
 SG_ M2P_BUS1_HVState_25 : 50|1@1+ (1,0) [0|1] ""  PC,SBMU
 SG_ M2P_BUS2_HVState_25 : 51|1@1+ (1,0) [0|1] ""  PC,SBMU
 SG_ M2P_BUS3_HVState_25 : 52|1@1+ (1,0) [0|1] ""  PC,SBMU
 SG_ M2P_BUS4_HVState_25 : 53|1@1+ (1,0) [0|1] ""  PC,SBMU
 SG_ M2P_BUS5_HVState_25 : 54|1@1+ (1,0) [0|1] ""  PC,SBMU
 SG_ M2P_BUS6_HVState_25 : 55|1@1+ (1,0) [0|1] ""  PC,SBMU
 SG_ M2P_BUS7_HVState_25 : 56|1@1+ (1,0) [0|1] ""  PC,SBMU
 SG_ M2P_BUS8_HVState_25 : 57|1@1+ (1,0) [0|1] ""  PC,SBMU
 SG_ M2P_BUS9_HVState_25 : 58|1@1+ (1,0) [0|1] ""  PC,SBMU
 SG_ M2P_BUS10_HVState_25 : 59|1@1+ (1,0) [0|1] ""  PC,SBMU
 SG_ M2P_BUS11_HVState_25 : 60|1@1+ (1,0) [0|1] ""  PC,SBMU
 SG_ M2P_BUS12_HVState_25 : 61|1@1+ (1,0) [0|1] ""  PC,SBMU

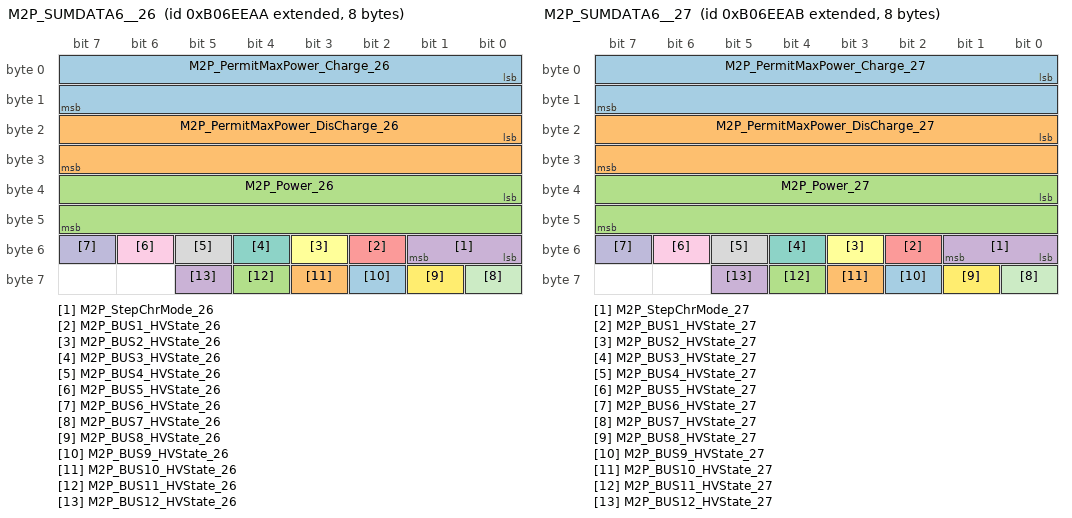
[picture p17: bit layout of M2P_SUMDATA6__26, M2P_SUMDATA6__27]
BO_ 2332487338 M2P_SUMDATA6__26: 8 MBMU
 SG_ M2P_PermitMaxPower_Charge_26 : 0|16@1+ (1,-20000) [0|45535] "Kw"  PC
 SG_ M2P_PermitMaxPower_DisCharge_26 : 16|16@1+ (1,-20000) [0|45535] "Kw"  PC
 SG_ M2P_Power_26 : 32|16@1+ (1,-20000) [0|45535] "Kw"  PC
 SG_ M2P_StepChrMode_26 : 48|2@1+ (1,0) [0|3] ""  PC
 SG_ M2P_BUS1_HVState_26 : 50|1@1+ (1,0) [0|1] ""  PC,SBMU
 SG_ M2P_BUS2_HVState_26 : 51|1@1+ (1,0) [0|1] ""  PC,SBMU
 SG_ M2P_BUS3_HVState_26 : 52|1@1+ (1,0) [0|1] ""  PC,SBMU
 SG_ M2P_BUS4_HVState_26 : 53|1@1+ (1,0) [0|1] ""  PC,SBMU
 SG_ M2P_BUS5_HVState_26 : 54|1@1+ (1,0) [0|1] ""  PC,SBMU
 SG_ M2P_BUS6_HVState_26 : 55|1@1+ (1,0) [0|1] ""  PC,SBMU
 SG_ M2P_BUS7_HVState_26 : 56|1@1+ (1,0) [0|1] ""  PC,SBMU
 SG_ M2P_BUS8_HVState_26 : 57|1@1+ (1,0) [0|1] ""  PC,SBMU
 SG_ M2P_BUS9_HVState_26 : 58|1@1+ (1,0) [0|1] ""  PC,SBMU
 SG_ M2P_BUS10_HVState_26 : 59|1@1+ (1,0) [0|1] ""  PC,SBMU
 SG_ M2P_BUS11_HVState_26 : 60|1@1+ (1,0) [0|1] ""  PC,SBMU
 SG_ M2P_BUS12_HVState_26 : 61|1@1+ (1,0) [0|1] ""  PC,SBMU

BO_ 2332487339 M2P_SUMDATA6__27: 8 MBMU
 SG_ M2P_PermitMaxPower_Charge_27 : 0|16@1+ (1,-20000) [0|45535] "Kw"  PC
 SG_ M2P_PermitMaxPower_DisCharge_27 : 16|16@1+ (1,-20000) [0|45535] "Kw"  PC
 SG_ M2P_Power_27 : 32|16@1+ (1,-20000) [0|45535] "Kw"  PC
 SG_ M2P_StepChrMode_27 : 48|2@1+ (1,0) [0|3] ""  PC
 SG_ M2P_BUS1_HVState_27 : 50|1@1+ (1,0) [0|1] ""  PC,SBMU
 SG_ M2P_BUS2_HVState_27 : 51|1@1+ (1,0) [0|1] ""  PC,SBMU
 SG_ M2P_BUS3_HVState_27 : 52|1@1+ (1,0) [0|1] ""  PC,SBMU
 SG_ M2P_BUS4_HVState_27 : 53|1@1+ (1,0) [0|1] ""  PC,SBMU
 SG_ M2P_BUS5_HVState_27 : 54|1@1+ (1,0) [0|1] ""  PC,SBMU
 SG_ M2P_BUS6_HVState_27 : 55|1@1+ (1,0) [0|1] ""  PC,SBMU
 SG_ M2P_BUS7_HVState_27 : 56|1@1+ (1,0) [0|1] ""  PC,SBMU
 SG_ M2P_BUS8_HVState_27 : 57|1@1+ (1,0) [0|1] ""  PC,SBMU
 SG_ M2P_BUS9_HVState_27 : 58|1@1+ (1,0) [0|1] ""  PC,SBMU
 SG_ M2P_BUS10_HVState_27 : 59|1@1+ (1,0) [0|1] ""  PC,SBMU
 SG_ M2P_BUS11_HVState_27 : 60|1@1+ (1,0) [0|1] ""  PC,SBMU
 SG_ M2P_BUS12_HVState_27 : 61|1@1+ (1,0) [0|1] ""  PC,SBMU

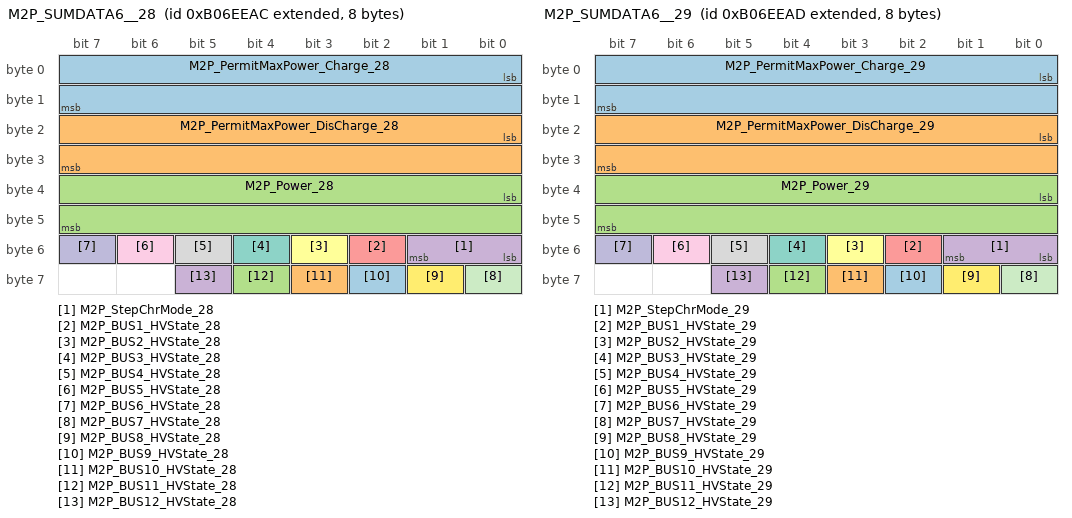
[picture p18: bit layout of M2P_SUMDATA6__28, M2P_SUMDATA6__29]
BO_ 2332487340 M2P_SUMDATA6__28: 8 MBMU
 SG_ M2P_PermitMaxPower_Charge_28 : 0|16@1+ (1,-20000) [0|45535] "Kw"  PC
 SG_ M2P_PermitMaxPower_DisCharge_28 : 16|16@1+ (1,-20000) [0|45535] "Kw"  PC
 SG_ M2P_Power_28 : 32|16@1+ (1,-20000) [0|45535] "Kw"  PC
 SG_ M2P_StepChrMode_28 : 48|2@1+ (1,0) [0|3] ""  PC
 SG_ M2P_BUS1_HVState_28 : 50|1@1+ (1,0) [0|1] ""  PC,SBMU
 SG_ M2P_BUS2_HVState_28 : 51|1@1+ (1,0) [0|1] ""  PC,SBMU
 SG_ M2P_BUS3_HVState_28 : 52|1@1+ (1,0) [0|1] ""  PC,SBMU
 SG_ M2P_BUS4_HVState_28 : 53|1@1+ (1,0) [0|1] ""  PC,SBMU
 SG_ M2P_BUS5_HVState_28 : 54|1@1+ (1,0) [0|1] ""  PC,SBMU
 SG_ M2P_BUS6_HVState_28 : 55|1@1+ (1,0) [0|1] ""  PC,SBMU
 SG_ M2P_BUS7_HVState_28 : 56|1@1+ (1,0) [0|1] ""  PC,SBMU
 SG_ M2P_BUS8_HVState_28 : 57|1@1+ (1,0) [0|1] ""  PC,SBMU
 SG_ M2P_BUS9_HVState_28 : 58|1@1+ (1,0) [0|1] ""  PC,SBMU
 SG_ M2P_BUS10_HVState_28 : 59|1@1+ (1,0) [0|1] ""  PC,SBMU
 SG_ M2P_BUS11_HVState_28 : 60|1@1+ (1,0) [0|1] ""  PC,SBMU
 SG_ M2P_BUS12_HVState_28 : 61|1@1+ (1,0) [0|1] ""  PC,SBMU

BO_ 2332487341 M2P_SUMDATA6__29: 8 MBMU
 SG_ M2P_PermitMaxPower_Charge_29 : 0|16@1+ (1,-20000) [0|45535] "Kw"  PC
 SG_ M2P_PermitMaxPower_DisCharge_29 : 16|16@1+ (1,-20000) [0|45535] "Kw"  PC
 SG_ M2P_Power_29 : 32|16@1+ (1,-20000) [0|45535] "Kw"  PC
 SG_ M2P_StepChrMode_29 : 48|2@1+ (1,0) [0|3] ""  PC
 SG_ M2P_BUS1_HVState_29 : 50|1@1+ (1,0) [0|1] ""  PC,SBMU
 SG_ M2P_BUS2_HVState_29 : 51|1@1+ (1,0) [0|1] ""  PC,SBMU
 SG_ M2P_BUS3_HVState_29 : 52|1@1+ (1,0) [0|1] ""  PC,SBMU
 SG_ M2P_BUS4_HVState_29 : 53|1@1+ (1,0) [0|1] ""  PC,SBMU
 SG_ M2P_BUS5_HVState_29 : 54|1@1+ (1,0) [0|1] ""  PC,SBMU
 SG_ M2P_BUS6_HVState_29 : 55|1@1+ (1,0) [0|1] ""  PC,SBMU
 SG_ M2P_BUS7_HVState_29 : 56|1@1+ (1,0) [0|1] ""  PC,SBMU
 SG_ M2P_BUS8_HVState_29 : 57|1@1+ (1,0) [0|1] ""  PC,SBMU
 SG_ M2P_BUS9_HVState_29 : 58|1@1+ (1,0) [0|1] ""  PC,SBMU
 SG_ M2P_BUS10_HVState_29 : 59|1@1+ (1,0) [0|1] ""  PC,SBMU
 SG_ M2P_BUS11_HVState_29 : 60|1@1+ (1,0) [0|1] ""  PC,SBMU
 SG_ M2P_BUS12_HVState_29 : 61|1@1+ (1,0) [0|1] ""  PC,SBMU

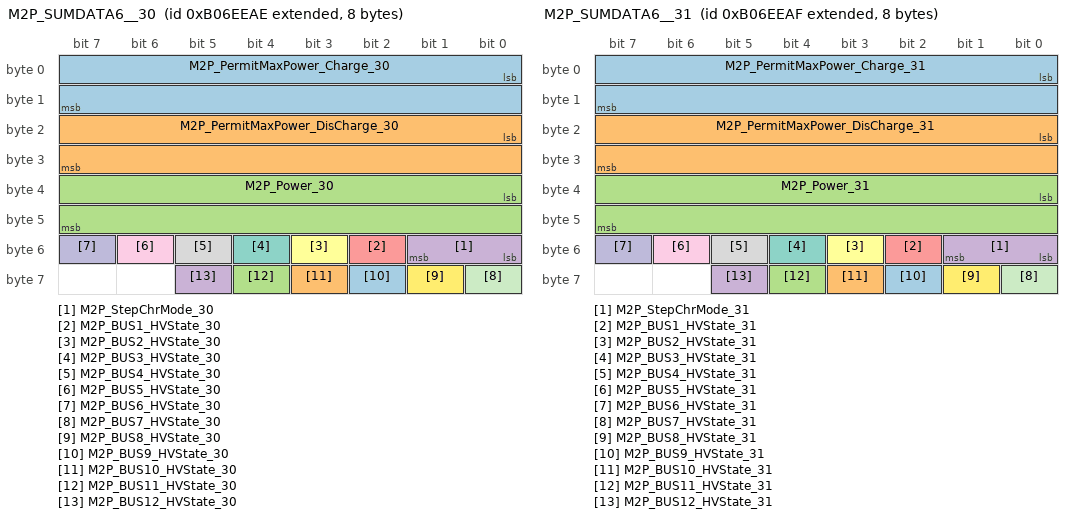
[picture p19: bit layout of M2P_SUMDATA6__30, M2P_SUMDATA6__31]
BO_ 2332487342 M2P_SUMDATA6__30: 8 MBMU
 SG_ M2P_PermitMaxPower_Charge_30 : 0|16@1+ (1,-20000) [0|45535] "Kw"  PC
 SG_ M2P_PermitMaxPower_DisCharge_30 : 16|16@1+ (1,-20000) [0|45535] "Kw"  PC
 SG_ M2P_Power_30 : 32|16@1+ (1,-20000) [0|45535] "Kw"  PC
 SG_ M2P_StepChrMode_30 : 48|2@1+ (1,0) [0|3] ""  PC
 SG_ M2P_BUS1_HVState_30 : 50|1@1+ (1,0) [0|1] ""  PC,SBMU
 SG_ M2P_BUS2_HVState_30 : 51|1@1+ (1,0) [0|1] ""  PC,SBMU
 SG_ M2P_BUS3_HVState_30 : 52|1@1+ (1,0) [0|1] ""  PC,SBMU
 SG_ M2P_BUS4_HVState_30 : 53|1@1+ (1,0) [0|1] ""  PC,SBMU
 SG_ M2P_BUS5_HVState_30 : 54|1@1+ (1,0) [0|1] ""  PC,SBMU
 SG_ M2P_BUS6_HVState_30 : 55|1@1+ (1,0) [0|1] ""  PC,SBMU
 SG_ M2P_BUS7_HVState_30 : 56|1@1+ (1,0) [0|1] ""  PC,SBMU
 SG_ M2P_BUS8_HVState_30 : 57|1@1+ (1,0) [0|1] ""  PC,SBMU
 SG_ M2P_BUS9_HVState_30 : 58|1@1+ (1,0) [0|1] ""  PC,SBMU
 SG_ M2P_BUS10_HVState_30 : 59|1@1+ (1,0) [0|1] ""  PC,SBMU
 SG_ M2P_BUS11_HVState_30 : 60|1@1+ (1,0) [0|1] ""  PC,SBMU
 SG_ M2P_BUS12_HVState_30 : 61|1@1+ (1,0) [0|1] ""  PC,SBMU

BO_ 2332487343 M2P_SUMDATA6__31: 8 MBMU
 SG_ M2P_PermitMaxPower_Charge_31 : 0|16@1+ (1,-20000) [0|45535] "Kw"  PC
 SG_ M2P_PermitMaxPower_DisCharge_31 : 16|16@1+ (1,-20000) [0|45535] "Kw"  PC
 SG_ M2P_Power_31 : 32|16@1+ (1,-20000) [0|45535] "Kw"  PC
 SG_ M2P_StepChrMode_31 : 48|2@1+ (1,0) [0|3] ""  PC
 SG_ M2P_BUS1_HVState_31 : 50|1@1+ (1,0) [0|1] ""  PC,SBMU
 SG_ M2P_BUS2_HVState_31 : 51|1@1+ (1,0) [0|1] ""  PC,SBMU
 SG_ M2P_BUS3_HVState_31 : 52|1@1+ (1,0) [0|1] ""  PC,SBMU
 SG_ M2P_BUS4_HVState_31 : 53|1@1+ (1,0) [0|1] ""  PC,SBMU
 SG_ M2P_BUS5_HVState_31 : 54|1@1+ (1,0) [0|1] ""  PC,SBMU
 SG_ M2P_BUS6_HVState_31 : 55|1@1+ (1,0) [0|1] ""  PC,SBMU
 SG_ M2P_BUS7_HVState_31 : 56|1@1+ (1,0) [0|1] ""  PC,SBMU
 SG_ M2P_BUS8_HVState_31 : 57|1@1+ (1,0) [0|1] ""  PC,SBMU
 SG_ M2P_BUS9_HVState_31 : 58|1@1+ (1,0) [0|1] ""  PC,SBMU
 SG_ M2P_BUS10_HVState_31 : 59|1@1+ (1,0) [0|1] ""  PC,SBMU
 SG_ M2P_BUS11_HVState_31 : 60|1@1+ (1,0) [0|1] ""  PC,SBMU
 SG_ M2P_BUS12_HVState_31 : 61|1@1+ (1,0) [0|1] ""  PC,SBMU

BO_ 2332552849 M2P_SUMDATA7__01: 8 MBMU
 SG_ M2P_SysremainEngy_Charge_01 : 0|16@1+ (1,0) [0|65535] "Kwh"  PC
 SG_ M2P_SysremainEngy_DisCharge_01 : 16|16@1+ (1,0) [0|65535] "Kwh"  PC
 SG_ M2P_SOE_Charge_01 : 32|10@1+ (0.1,0) [0|102.3] "%"  PC
 SG_ M2P_SOE_Discharge_01 : 42|10@1+ (0.1,0) [0|102.3] "%"  PC

BO_ 2332552850 M2P_SUMDATA7__02: 8 MBMU
 SG_ M2P_SysremainEngy_Charge_02 : 0|16@1+ (1,0) [0|65535] "Kwh"  PC
 SG_ M2P_SysremainEngy_DisCharge_02 : 16|16@1+ (1,0) [0|65535] "Kwh"  PC
 SG_ M2P_SOE_Charge_02 : 32|10@1+ (0.1,0) [0|102.3] "%"  PC
 SG_ M2P_SOE_Discharge_02 : 42|10@1+ (0.1,0) [0|102.3] "%"  PC

BO_ 2332552851 M2P_SUMDATA7__03: 8 MBMU
 SG_ M2P_SysremainEngy_Charge_03 : 0|16@1+ (1,0) [0|65535] "Kwh"  PC
 SG_ M2P_SysremainEngy_DisCharge_03 : 16|16@1+ (1,0) [0|65535] "Kwh"  PC
 SG_ M2P_SOE_Charge_03 : 32|10@1+ (0.1,0) [0|102.3] "%"  PC
 SG_ M2P_SOE_Discharge_03 : 42|10@1+ (0.1,0) [0|102.3] "%"  PC

BO_ 2332552852 M2P_SUMDATA7__04: 8 MBMU
 SG_ M2P_SysremainEngy_Charge_04 : 0|16@1+ (1,0) [0|65535] "Kwh"  PC
 SG_ M2P_SysremainEngy_DisCharge_04 : 16|16@1+ (1,0) [0|65535] "Kwh"  PC
 SG_ M2P_SOE_Charge_04 : 32|10@1+ (0.1,0) [0|102.3] "%"  PC
 SG_ M2P_SOE_Discharge_04 : 42|10@1+ (0.1,0) [0|102.3] "%"  PC

BO_ 2332552853 M2P_SUMDATA7__05: 8 MBMU
 SG_ M2P_SysremainEngy_Charge_05 : 0|16@1+ (1,0) [0|65535] "Kwh"  PC
 SG_ M2P_SysremainEngy_DisCharge_05 : 16|16@1+ (1,0) [0|65535] "Kwh"  PC
 SG_ M2P_SOE_Charge_05 : 32|10@1+ (0.1,0) [0|102.3] "%"  PC
 SG_ M2P_SOE_Discharge_05 : 42|10@1+ (0.1,0) [0|102.3] "%"  PC

BO_ 2332552854 M2P_SUMDATA7__06: 8 MBMU
 SG_ M2P_SysremainEngy_Charge_06 : 0|16@1+ (1,0) [0|65535] "Kwh"  PC
 SG_ M2P_SysremainEngy_DisCharge_06 : 16|16@1+ (1,0) [0|65535] "Kwh"  PC
 SG_ M2P_SOE_Charge_06 : 32|10@1+ (0.1,0) [0|102.3] "%"  PC
 SG_ M2P_SOE_Discharge_06 : 42|10@1+ (0.1,0) [0|102.3] "%"  PC

BO_ 2332552855 M2P_SUMDATA7__07: 8 MBMU
 SG_ M2P_SysremainEngy_Charge_07 : 0|16@1+ (1,0) [0|65535] "Kwh"  PC
 SG_ M2P_SysremainEngy_DisCharge_07 : 16|16@1+ (1,0) [0|65535] "Kwh"  PC
 SG_ M2P_SOE_Charge_07 : 32|10@1+ (0.1,0) [0|102.3] "%"  PC
 SG_ M2P_SOE_Discharge_07 : 42|10@1+ (0.1,0) [0|102.3] "%"  PC

BO_ 2332552856 M2P_SUMDATA7__08: 8 MBMU
 SG_ M2P_SysremainEngy_Charge_08 : 0|16@1+ (1,0) [0|65535] "Kwh"  PC
 SG_ M2P_SysremainEngy_DisCharge_08 : 16|16@1+ (1,0) [0|65535] "Kwh"  PC
 SG_ M2P_SOE_Charge_08 : 32|10@1+ (0.1,0) [0|102.3] "%"  PC
 SG_ M2P_SOE_Discharge_08 : 42|10@1+ (0.1,0) [0|102.3] "%"  PC

BO_ 2332552857 M2P_SUMDATA7__09: 8 MBMU
 SG_ M2P_SysremainEngy_Charge_09 : 0|16@1+ (1,0) [0|65535] "Kwh"  PC
 SG_ M2P_SysremainEngy_DisCharge_09 : 16|16@1+ (1,0) [0|65535] "Kwh"  PC
 SG_ M2P_SOE_Charge_09 : 32|10@1+ (0.1,0) [0|102.3] "%"  PC
 SG_ M2P_SOE_Discharge_09 : 42|10@1+ (0.1,0) [0|102.3] "%"  PC

BO_ 2332552858 M2P_SUMDATA7__10: 8 MBMU
 SG_ M2P_SysremainEngy_Charge_10 : 0|16@1+ (1,0) [0|65535] "Kwh"  PC
 SG_ M2P_SysremainEngy_DisCharge_10 : 16|16@1+ (1,0) [0|65535] "Kwh"  PC
 SG_ M2P_SOE_Charge_10 : 32|10@1+ (0.1,0) [0|102.3] "%"  PC
 SG_ M2P_SOE_Discharge_10 : 42|10@1+ (0.1,0) [0|102.3] "%"  PC

BO_ 2332552859 M2P_SUMDATA7__11: 8 MBMU
 SG_ M2P_SysremainEngy_Charge_11 : 0|16@1+ (1,0) [0|65535] "Kwh"  PC
 SG_ M2P_SysremainEngy_DisCharge_11 : 16|16@1+ (1,0) [0|65535] "Kwh"  PC
 SG_ M2P_SOE_Charge_11 : 32|10@1+ (0.1,0) [0|102.3] "%"  PC
 SG_ M2P_SOE_Discharge_11 : 42|10@1+ (0.1,0) [0|102.3] "%"  PC

BO_ 2332552860 M2P_SUMDATA7__12: 8 MBMU
 SG_ M2P_SysremainEngy_Charge_12 : 0|16@1+ (1,0) [0|65535] "Kwh"  PC
 SG_ M2P_SysremainEngy_DisCharge_12 : 16|16@1+ (1,0) [0|65535] "Kwh"  PC
 SG_ M2P_SOE_Charge_12 : 32|10@1+ (0.1,0) [0|102.3] "%"  PC
 SG_ M2P_SOE_Discharge_12 : 42|10@1+ (0.1,0) [0|102.3] "%"  PC

BO_ 2332552861 M2P_SUMDATA7__13: 8 MBMU
 SG_ M2P_SysremainEngy_Charge_13 : 0|16@1+ (1,0) [0|65535] "Kwh"  PC
 SG_ M2P_SysremainEngy_DisCharge_13 : 16|16@1+ (1,0) [0|65535] "Kwh"  PC
 SG_ M2P_SOE_Charge_13 : 32|10@1+ (0.1,0) [0|102.3] "%"  PC
 SG_ M2P_SOE_Discharge_13 : 42|10@1+ (0.1,0) [0|102.3] "%"  PC

BO_ 2332552862 M2P_SUMDATA7__14: 8 MBMU
 SG_ M2P_SysremainEngy_Charge_14 : 0|16@1+ (1,0) [0|65535] "Kwh"  PC
 SG_ M2P_SysremainEngy_DisCharge_14 : 16|16@1+ (1,0) [0|65535] "Kwh"  PC
 SG_ M2P_SOE_Charge_14 : 32|10@1+ (0.1,0) [0|102.3] "%"  PC
 SG_ M2P_SOE_Discharge_14 : 42|10@1+ (0.1,0) [0|102.3] "%"  PC

BO_ 2332552863 M2P_SUMDATA7__15: 8 MBMU
 SG_ M2P_SysremainEngy_Charge_15 : 0|16@1+ (1,0) [0|65535] "Kwh"  PC
 SG_ M2P_SysremainEngy_DisCharge_15 : 16|16@1+ (1,0) [0|65535] "Kwh"  PC
 SG_ M2P_SOE_Charge_15 : 32|10@1+ (0.1,0) [0|102.3] "%"  PC
 SG_ M2P_SOE_Discharge_15 : 42|10@1+ (0.1,0) [0|102.3] "%"  PC

BO_ 2332552864 M2P_SUMDATA7__16: 8 MBMU
 SG_ M2P_SysremainEngy_Charge_16 : 0|16@1+ (1,0) [0|65535] "Kwh"  PC
 SG_ M2P_SysremainEngy_DisCharge_16 : 16|16@1+ (1,0) [0|65535] "Kwh"  PC
 SG_ M2P_SOE_Charge_16 : 32|10@1+ (0.1,0) [0|102.3] "%"  PC
 SG_ M2P_SOE_Discharge_16 : 42|10@1+ (0.1,0) [0|102.3] "%"  PC

BO_ 2332552865 M2P_SUMDATA7__17: 8 MBMU
 SG_ M2P_SysremainEngy_Charge_17 : 0|16@1+ (1,0) [0|65535] "Kwh"  PC
 SG_ M2P_SysremainEngy_DisCharge_17 : 16|16@1+ (1,0) [0|65535] "Kwh"  PC
 SG_ M2P_SOE_Charge_17 : 32|10@1+ (0.1,0) [0|102.3] "%"  PC
 SG_ M2P_SOE_Discharge_17 : 42|10@1+ (0.1,0) [0|102.3] "%"  PC

BO_ 2332552866 M2P_SUMDATA7__18: 8 MBMU
 SG_ M2P_SysremainEngy_Charge_18 : 0|16@1+ (1,0) [0|65535] "Kwh"  PC
 SG_ M2P_SysremainEngy_DisCharge_18 : 16|16@1+ (1,0) [0|65535] "Kwh"  PC
 SG_ M2P_SOE_Charge_18 : 32|10@1+ (0.1,0) [0|102.3] "%"  PC
 SG_ M2P_SOE_Discharge_18 : 42|10@1+ (0.1,0) [0|102.3] "%"  PC

BO_ 2332552867 M2P_SUMDATA7__19: 8 MBMU
 SG_ M2P_SysremainEngy_Charge_19 : 0|16@1+ (1,0) [0|65535] "Kwh"  PC
 SG_ M2P_SysremainEngy_DisCharge_19 : 16|16@1+ (1,0) [0|65535] "Kwh"  PC
 SG_ M2P_SOE_Charge_19 : 32|10@1+ (0.1,0) [0|102.3] "%"  PC
 SG_ M2P_SOE_Discharge_19 : 42|10@1+ (0.1,0) [0|102.3] "%"  PC

BO_ 2332552868 M2P_SUMDATA7__20: 8 MBMU
 SG_ M2P_SysremainEngy_Charge_20 : 0|16@1+ (1,0) [0|65535] "Kwh"  PC
 SG_ M2P_SysremainEngy_DisCharge_20 : 16|16@1+ (1,0) [0|65535] "Kwh"  PC
 SG_ M2P_SOE_Charge_20 : 32|10@1+ (0.1,0) [0|102.3] "%"  PC
 SG_ M2P_SOE_Discharge_20 : 42|10@1+ (0.1,0) [0|102.3] "%"  PC

BO_ 2332552869 M2P_SUMDATA7__21: 8 MBMU
 SG_ M2P_SysremainEngy_Charge_21 : 0|16@1+ (1,0) [0|65535] "Kwh"  PC
 SG_ M2P_SysremainEngy_DisCharge_21 : 16|16@1+ (1,0) [0|65535] "Kwh"  PC
 SG_ M2P_SOE_Charge_21 : 32|10@1+ (0.1,0) [0|102.3] "%"  PC
 SG_ M2P_SOE_Discharge_21 : 42|10@1+ (0.1,0) [0|102.3] "%"  PC

BO_ 2332552870 M2P_SUMDATA7__22: 8 MBMU
 SG_ M2P_SysremainEngy_Charge_22 : 0|16@1+ (1,0) [0|65535] "Kwh"  PC
 SG_ M2P_SysremainEngy_DisCharge_22 : 16|16@1+ (1,0) [0|65535] "Kwh"  PC
 SG_ M2P_SOE_Charge_22 : 32|10@1+ (0.1,0) [0|102.3] "%"  PC
 SG_ M2P_SOE_Discharge_22 : 42|10@1+ (0.1,0) [0|102.3] "%"  PC

BO_ 2332552871 M2P_SUMDATA7__23: 8 MBMU
 SG_ M2P_SysremainEngy_Charge_23 : 0|16@1+ (1,0) [0|65535] "Kwh"  PC
 SG_ M2P_SysremainEngy_DisCharge_23 : 16|16@1+ (1,0) [0|65535] "Kwh"  PC
 SG_ M2P_SOE_Charge_23 : 32|10@1+ (0.1,0) [0|102.3] "%"  PC
 SG_ M2P_SOE_Discharge_23 : 42|10@1+ (0.1,0) [0|102.3] "%"  PC

BO_ 2332552872 M2P_SUMDATA7__24: 8 MBMU
 SG_ M2P_SysremainEngy_Charge_24 : 0|16@1+ (1,0) [0|65535] "Kwh"  PC
 SG_ M2P_SysremainEngy_DisCharge_24 : 16|16@1+ (1,0) [0|65535] "Kwh"  PC
 SG_ M2P_SOE_Charge_24 : 32|10@1+ (0.1,0) [0|102.3] "%"  PC
 SG_ M2P_SOE_Discharge_24 : 42|10@1+ (0.1,0) [0|102.3] "%"  PC

BO_ 2332552873 M2P_SUMDATA7__25: 8 MBMU
 SG_ M2P_SysremainEngy_Charge_25 : 0|16@1+ (1,0) [0|65535] "Kwh"  PC
 SG_ M2P_SysremainEngy_DisCharge_25 : 16|16@1+ (1,0) [0|65535] "Kwh"  PC
 SG_ M2P_SOE_Charge_25 : 32|10@1+ (0.1,0) [0|102.3] "%"  PC
 SG_ M2P_SOE_Discharge_25 : 42|10@1+ (0.1,0) [0|102.3] "%"  PC

BO_ 2332552874 M2P_SUMDATA7__26: 8 MBMU
 SG_ M2P_SysremainEngy_Charge_26 : 0|16@1+ (1,0) [0|65535] "Kwh"  PC
 SG_ M2P_SysremainEngy_DisCharge_26 : 16|16@1+ (1,0) [0|65535] "Kwh"  PC
 SG_ M2P_SOE_Charge_26 : 32|10@1+ (0.1,0) [0|102.3] "%"  PC
 SG_ M2P_SOE_Discharge_26 : 42|10@1+ (0.1,0) [0|102.3] "%"  PC

CM_ SG_ 2332290731 M2P_PermitMaxCharge_I_27 "最大允许充电电流";
CM_ SG_ 2332290731 M2P_PermitMaxDisCharge_I_27 "最大允许放电电流";
CM_ SG_ 2332290731 M2P_Evn_T1_27 "MBMU环境温度1";
CM_ SG_ 2332290731 M2P_Evn_T2_27 "MBMU环境温度2";
CM_ SG_ 2332290731 M2P_Evn_T3_27 "MBMU环境温度3";
CM_ SG_ 2332290731 M2P_Evn_Humidity_27 "MBMU环境湿度";
CM_ SG_ 2332290732 M2P_PermitMaxCharge_I_28 "最大允许充电电流";
CM_ SG_ 2332290732 M2P_PermitMaxDisCharge_I_28 "最大允许放电电流";
CM_ SG_ 2332290732 M2P_Evn_T1_28 "MBMU环境温度1";
CM_ SG_ 2332290732 M2P_Evn_T2_28 "MBMU环境温度2";
CM_ SG_ 2332290732 M2P_Evn_T3_28 "MBMU环境温度3";
CM_ SG_ 2332290732 M2P_Evn_Humidity_28 "MBMU环境湿度";
CM_ SG_ 2332290733 M2P_PermitMaxCharge_I_29 "最大允许充电电流";
CM_ SG_ 2332290733 M2P_PermitMaxDisCharge_I_29 "最大允许放电电流";
CM_ SG_ 2332290733 M2P_Evn_T1_29 "MBMU环境温度1";
CM_ SG_ 2332290733 M2P_Evn_T2_29 "MBMU环境温度2";
CM_ SG_ 2332290733 M2P_Evn_T3_29 "MBMU环境温度3";
CM_ SG_ 2332290733 M2P_Evn_Humidity_29 "MBMU环境湿度";
CM_ SG_ 2332290734 M2P_PermitMaxCharge_I_30 "最大允许充电电流";
CM_ SG_ 2332290734 M2P_PermitMaxDisCharge_I_30 "最大允许放电电流";
CM_ SG_ 2332290734 M2P_Evn_T1_30 "MBMU环境温度1";
CM_ SG_ 2332290734 M2P_Evn_T2_30 "MBMU环境温度2";
CM_ SG_ 2332290734 M2P_Evn_T3_30 "MBMU环境温度3";
CM_ SG_ 2332290734 M2P_Evn_Humidity_30 "MBMU环境湿度";
CM_ SG_ 2332290735 M2P_PermitMaxCharge_I_31 "最大允许充电电流";
CM_ SG_ 2332290735 M2P_PermitMaxDisCharge_I_31 "最大允许放电电流";
CM_ SG_ 2332290735 M2P_Evn_T1_31 "MBMU环境温度1";
CM_ SG_ 2332290735 M2P_Evn_T2_31 "MBMU环境温度2";
CM_ SG_ 2332290735 M2P_Evn_T3_31 "MBMU环境温度3";
CM_ SG_ 2332290735 M2P_Evn_Humidity_31 "MBMU环境湿度";
CM_ SG_ 2332356241 M2P_SysMaxVolt_01 "系统单体最大电压  ";
CM_ SG_ 2332356241 M2P_SysMinVolt_01 "系统单体最小电压";
CM_ SG_ 2332356241 M2P_SysAvgVolt_01 "系统单体平均电压";
CM_ SG_ 2332356241 M2P_Evn_T4_01 "MBMU环境温度4";
CM_ SG_ 2332356241 M2P_Bat_CorrectState_Require_01 "MBMU请求进入维护修正模式";
CM_ SG_ 2332356242 M2P_SysMaxVolt_02 "系统单体最大电压  ";
CM_ SG_ 2332356242 M2P_SysMinVolt_02 "系统单体最小电压";
CM_ SG_ 2332356242 M2P_SysAvgVolt_02 "系统单体平均电压";
CM_ SG_ 2332356242 M2P_Evn_T4_02 "MBMU环境温度4";
CM_ SG_ 2332356242 M2P_Bat_CorrectState_Require_02 "MBMU请求进入维护修正模式";
CM_ SG_ 2332356243 M2P_SysMaxVolt_03 "系统单体最大电压  ";
CM_ SG_ 2332356243 M2P_SysMinVolt_03 "系统单体最小电压";
CM_ SG_ 2332356243 M2P_SysAvgVolt_03 "系统单体平均电压";
CM_ SG_ 2332356243 M2P_Evn_T4_03 "MBMU环境温度4";
CM_ SG_ 2332356243 M2P_Bat_CorrectState_Require_03 "MBMU请求进入维护修正模式";
CM_ SG_ 2332356244 M2P_SysMaxVolt_04 "系统单体最大电压  ";
CM_ SG_ 2332356244 M2P_SysMinVolt_04 "系统单体最小电压";
CM_ SG_ 2332356244 M2P_SysAvgVolt_04 "系统单体平均电压";
CM_ SG_ 2332356244 M2P_Evn_T4_04 "MBMU环境温度4";
CM_ SG_ 2332356244 M2P_Bat_CorrectState_Require_04 "MBMU请求进入维护修正模式";
CM_ SG_ 2332356245 M2P_SysMaxVolt_05 "系统单体最大电压  ";
CM_ SG_ 2332356245 M2P_SysMinVolt_05 "系统单体最小电压";
CM_ SG_ 2332356245 M2P_SysAvgVolt_05 "系统单体平均电压";
CM_ SG_ 2332356245 M2P_Evn_T4_05 "MBMU环境温度4";
CM_ SG_ 2332356245 M2P_Bat_CorrectState_Require_05 "MBMU请求进入维护修正模式";
CM_ SG_ 2332356246 M2P_SysMaxVolt_06 "系统单体最大电压  ";
CM_ SG_ 2332356246 M2P_SysMinVolt_06 "系统单体最小电压";
CM_ SG_ 2332356246 M2P_SysAvgVolt_06 "系统单体平均电压";
CM_ SG_ 2332356246 M2P_Evn_T4_06 "MBMU环境温度4";
CM_ SG_ 2332356246 M2P_Bat_CorrectState_Require_06 "MBMU请求进入维护修正模式";
CM_ SG_ 2332356247 M2P_SysMaxVolt_07 "系统单体最大电压  ";
CM_ SG_ 2332356247 M2P_SysMinVolt_07 "系统单体最小电压";
CM_ SG_ 2332356247 M2P_SysAvgVolt_07 "系统单体平均电压";
CM_ SG_ 2332356247 M2P_Evn_T4_07 "MBMU环境温度4";
CM_ SG_ 2332356247 M2P_Bat_CorrectState_Require_07 "MBMU请求进入维护修正模式";
CM_ SG_ 2332356248 M2P_SysMaxVolt_08 "系统单体最大电压  ";
CM_ SG_ 2332356248 M2P_SysMinVolt_08 "系统单体最小电压";
CM_ SG_ 2332356248 M2P_SysAvgVolt_08 "系统单体平均电压";
CM_ SG_ 2332356248 M2P_Evn_T4_08 "MBMU环境温度4";
CM_ SG_ 2332356248 M2P_Bat_CorrectState_Require_08 "MBMU请求进入维护修正模式";
CM_ SG_ 2332356249 M2P_SysMaxVolt_09 "系统单体最大电压  ";
CM_ SG_ 2332356249 M2P_SysMinVolt_09 "系统单体最小电压";
CM_ SG_ 2332356249 M2P_SysAvgVolt_09 "系统单体平均电压";
CM_ SG_ 2332356249 M2P_Evn_T4_09 "MBMU环境温度4";
CM_ SG_ 2332356249 M2P_Bat_CorrectState_Require_09 "MBMU请求进入维护修正模式";
CM_ SG_ 2332356250 M2P_SysMaxVolt_10 "系统单体最大电压  ";
CM_ SG_ 2332356250 M2P_SysMinVolt_10 "系统单体最小电压";
CM_ SG_ 2332356250 M2P_SysAvgVolt_10 "系统单体平均电压";
CM_ SG_ 2332356250 M2P_Evn_T4_10 "MBMU环境温度4";
CM_ SG_ 2332356250 M2P_Bat_CorrectState_Require_10 "MBMU请求进入维护修正模式";
CM_ SG_ 2332356251 M2P_SysMaxVolt_11 "系统单体最大电压  ";
CM_ SG_ 2332356251 M2P_SysMinVolt_11 "系统单体最小电压";
CM_ SG_ 2332356251 M2P_SysAvgVolt_11 "系统单体平均电压";
CM_ SG_ 2332356251 M2P_Evn_T4_11 "MBMU环境温度4";
CM_ SG_ 2332356251 M2P_Bat_CorrectState_Require_11 "MBMU请求进入维护修正模式";
CM_ SG_ 2332356252 M2P_SysMaxVolt_12 "系统单体最大电压  ";
CM_ SG_ 2332356252 M2P_SysMinVolt_12 "系统单体最小电压";
CM_ SG_ 2332356252 M2P_SysAvgVolt_12 "系统单体平均电压";
CM_ SG_ 2332356252 M2P_Evn_T4_12 "MBMU环境温度4";
CM_ SG_ 2332356252 M2P_Bat_CorrectState_Require_12 "MBMU请求进入维护修正模式";
CM_ SG_ 2332356253 M2P_SysMaxVolt_13 "系统单体最大电压  ";
CM_ SG_ 2332356253 M2P_SysMinVolt_13 "系统单体最小电压";
CM_ SG_ 2332356253 M2P_SysAvgVolt_13 "系统单体平均电压";
CM_ SG_ 2332356253 M2P_Evn_T4_13 "MBMU环境温度4";
CM_ SG_ 2332356253 M2P_Bat_CorrectState_Require_13 "MBMU请求进入维护修正模式";
CM_ SG_ 2332356254 M2P_SysMaxVolt_14 "系统单体最大电压  ";
CM_ SG_ 2332356254 M2P_SysMinVolt_14 "系统单体最小电压";
CM_ SG_ 2332356254 M2P_SysAvgVolt_14 "系统单体平均电压";
CM_ SG_ 2332356254 M2P_Evn_T4_14 "MBMU环境温度4";
CM_ SG_ 2332356254 M2P_Bat_CorrectState_Require_14 "MBMU请求进入维护修正模式";
CM_ SG_ 2332356255 M2P_SysMaxVolt_15 "系统单体最大电压  ";
CM_ SG_ 2332356255 M2P_SysMinVolt_15 "系统单体最小电压";
CM_ SG_ 2332356255 M2P_SysAvgVolt_15 "系统单体平均电压";
CM_ SG_ 2332356255 M2P_Evn_T4_15 "MBMU环境温度4";
CM_ SG_ 2332356255 M2P_Bat_CorrectState_Require_15 "MBMU请求进入维护修正模式";
CM_ SG_ 2332356256 M2P_SysMaxVolt_16 "系统单体最大电压  ";
CM_ SG_ 2332356256 M2P_SysMinVolt_16 "系统单体最小电压";
CM_ SG_ 2332356256 M2P_SysAvgVolt_16 "系统单体平均电压";
CM_ SG_ 2332356256 M2P_Evn_T4_16 "MBMU环境温度4";
CM_ SG_ 2332356256 M2P_Bat_CorrectState_Require_16 "MBMU请求进入维护修正模式";
CM_ SG_ 2332356257 M2P_SysMaxVolt_17 "系统单体最大电压  ";
CM_ SG_ 2332356257 M2P_SysMinVolt_17 "系统单体最小电压";
CM_ SG_ 2332356257 M2P_SysAvgVolt_17 "系统单体平均电压";
CM_ SG_ 2332356257 M2P_Evn_T4_17 "MBMU环境温度4";
CM_ SG_ 2332356257 M2P_Bat_CorrectState_Require_17 "MBMU请求进入维护修正模式";
CM_ SG_ 2332356258 M2P_SysMaxVolt_18 "系统单体最大电压  ";
CM_ SG_ 2332356258 M2P_SysMinVolt_18 "系统单体最小电压";
CM_ SG_ 2332356258 M2P_SysAvgVolt_18 "系统单体平均电压";
CM_ SG_ 2332356258 M2P_Evn_T4_18 "MBMU环境温度4";
CM_ SG_ 2332356258 M2P_Bat_CorrectState_Require_18 "MBMU请求进入维护修正模式";
CM_ SG_ 2332356259 M2P_SysMaxVolt_19 "系统单体最大电压  ";
CM_ SG_ 2332356259 M2P_SysMinVolt_19 "系统单体最小电压";
CM_ SG_ 2332356259 M2P_SysAvgVolt_19 "系统单体平均电压";
CM_ SG_ 2332356259 M2P_Evn_T4_19 "MBMU环境温度4";
CM_ SG_ 2332356259 M2P_Bat_CorrectState_Require_19 "MBMU请求进入维护修正模式";
CM_ SG_ 2332356260 M2P_SysMaxVolt_20 "系统单体最大电压  ";
CM_ SG_ 2332356260 M2P_SysMinVolt_20 "系统单体最小电压";
CM_ SG_ 2332356260 M2P_SysAvgVolt_20 "系统单体平均电压";
CM_ SG_ 2332356260 M2P_Evn_T4_20 "MBMU环境温度4";
CM_ SG_ 2332356260 M2P_Bat_CorrectState_Require_20 "MBMU请求进入维护修正模式";
CM_ SG_ 2332356261 M2P_SysMaxVolt_21 "系统单体最大电压  ";
CM_ SG_ 2332356261 M2P_SysMinVolt_21 "系统单体最小电压";
CM_ SG_ 2332356261 M2P_SysAvgVolt_21 "系统单体平均电压";
CM_ SG_ 2332356261 M2P_Evn_T4_21 "MBMU环境温度4";
CM_ SG_ 2332356261 M2P_Bat_CorrectState_Require_21 "MBMU请求进入维护修正模式";
CM_ SG_ 2332356262 M2P_SysMaxVolt_22 "系统单体最大电压  ";
CM_ SG_ 2332356262 M2P_SysMinVolt_22 "系统单体最小电压";
CM_ SG_ 2332356262 M2P_SysAvgVolt_22 "系统单体平均电压";
CM_ SG_ 2332356262 M2P_Evn_T4_22 "MBMU环境温度4";
CM_ SG_ 2332356262 M2P_Bat_CorrectState_Require_22 "MBMU请求进入维护修正模式";
CM_ SG_ 2332356263 M2P_SysMaxVolt_23 "系统单体最大电压  ";
CM_ SG_ 2332356263 M2P_SysMinVolt_23 "系统单体最小电压";
CM_ SG_ 2332356263 M2P_SysAvgVolt_23 "系统单体平均电压";
CM_ SG_ 2332356263 M2P_Evn_T4_23 "MBMU环境温度4";
CM_ SG_ 2332356263 M2P_Bat_CorrectState_Require_23 "MBMU请求进入维护修正模式";
CM_ SG_ 2332356264 M2P_SysMaxVolt_24 "系统单体最大电压  ";
CM_ SG_ 2332356264 M2P_SysMinVolt_24 "系统单体最小电压";
CM_ SG_ 2332356264 M2P_SysAvgVolt_24 "系统单体平均电压";
CM_ SG_ 2332356264 M2P_Evn_T4_24 "MBMU环境温度4";
CM_ SG_ 2332356264 M2P_Bat_CorrectState_Require_24 "MBMU请求进入维护修正模式";
CM_ SG_ 2332356265 M2P_SysMaxVolt_25 "系统单体最大电压  ";
CM_ SG_ 2332356265 M2P_SysMinVolt_25 "系统单体最小电压";
CM_ SG_ 2332356265 M2P_SysAvgVolt_25 "系统单体平均电压";
CM_ SG_ 2332356265 M2P_Evn_T4_25 "MBMU环境温度4";
CM_ SG_ 2332356265 M2P_Bat_CorrectState_Require_25 "MBMU请求进入维护修正模式";
CM_ SG_ 2332356266 M2P_SysMaxVolt_26 "系统单体最大电压  ";
CM_ SG_ 2332356266 M2P_SysMinVolt_26 "系统单体最小电压";
CM_ SG_ 2332356266 M2P_SysAvgVolt_26 "系统单体平均电压";
CM_ SG_ 2332356266 M2P_Evn_T4_26 "MBMU环境温度4";
CM_ SG_ 2332356266 M2P_Bat_CorrectState_Require_26 "MBMU请求进入维护修正模式";
CM_ SG_ 2332356267 M2P_SysMaxVolt_27 "系统单体最大电压  ";
CM_ SG_ 2332356267 M2P_SysMinVolt_27 "系统单体最小电压";
CM_ SG_ 2332356267 M2P_SysAvgVolt_27 "系统单体平均电压";
CM_ SG_ 2332356267 M2P_Evn_T4_27 "MBMU环境温度4";
CM_ SG_ 2332356267 M2P_Bat_CorrectState_Require_27 "MBMU请求进入维护修正模式";
CM_ SG_ 2332356268 M2P_SysMaxVolt_28 "系统单体最大电压  ";
CM_ SG_ 2332356268 M2P_SysMinVolt_28 "系统单体最小电压";
CM_ SG_ 2332356268 M2P_SysAvgVolt_28 "系统单体平均电压";
CM_ SG_ 2332356268 M2P_Evn_T4_28 "MBMU环境温度4";
CM_ SG_ 2332356268 M2P_Bat_CorrectState_Require_28 "MBMU请求进入维护修正模式";
CM_ SG_ 2332356269 M2P_SysMaxVolt_29 "系统单体最大电压  ";
CM_ SG_ 2332356269 M2P_SysMinVolt_29 "系统单体最小电压";
CM_ SG_ 2332356269 M2P_SysAvgVolt_29 "系统单体平均电压";
CM_ SG_ 2332356269 M2P_Evn_T4_29 "MBMU环境温度4";
CM_ SG_ 2332356269 M2P_Bat_CorrectState_Require_29 "MBMU请求进入维护修正模式";
CM_ SG_ 2332356270 M2P_SysMaxVolt_30 "系统单体最大电压  ";
CM_ SG_ 2332356270 M2P_SysMinVolt_30 "系统单体最小电压";
CM_ SG_ 2332356270 M2P_SysAvgVolt_30 "系统单体平均电压";
CM_ SG_ 2332356270 M2P_Evn_T4_30 "MBMU环境温度4";
CM_ SG_ 2332356270 M2P_Bat_CorrectState_Require_30 "MBMU请求进入维护修正模式";
CM_ SG_ 2332356271 M2P_SysMaxVolt_31 "系统单体最大电压  ";
CM_ SG_ 2332356271 M2P_SysMinVolt_31 "系统单体最小电压";
CM_ SG_ 2332356271 M2P_SysAvgVolt_31 "系统单体平均电压";
CM_ SG_ 2332356271 M2P_Evn_T4_31 "MBMU环境温度4";
CM_ SG_ 2332356271 M2P_Bat_CorrectState_Require_31 "MBMU请求进入维护修正模式";
CM_ SG_ 2332421777 M2P_SysMaxTemp_01 "MBMU电芯最高温度";
CM_ SG_ 2332421777 M2P_SysMinTemp_01 "MBMU电芯最低温度";
CM_ SG_ 2332421777 M2P_SysAvgTemp_01 "MBMU电芯平均温度";
CM_ SG_ 2332421777 M2P_PermitMaxVolt_01 "最高允许充电电压 （配置量）";
CM_ SG_ 2332421777 M2P_PermitMinVolt_01 "最低允许放电电压 （配置量）";
CM_ SG_ 2332421777 M2P_TMSCalibration_01 "水冷机组ID标定量";
CM_ SG_ 2332421777 M2P_IsoDetfunctionStatus_01 "绝缘检测功能状态";
CM_ SG_ 2332421777 M2P_TMS_Address_infor_01 "水冷机组编号";
CM_ SG_ 2332421778 M2P_SysMaxTemp_02 "MBMU电芯最高温度";
CM_ SG_ 2332421778 M2P_SysMinTemp_02 "MBMU电芯最低温度";
CM_ SG_ 2332421778 M2P_SysAvgTemp_02 "MBMU电芯平均温度";
CM_ SG_ 2332421778 M2P_PermitMaxVolt_02 "最高允许充电电压 （配置量）";
CM_ SG_ 2332421778 M2P_PermitMinVolt_02 "最低允许放电电压 （配置量）";
CM_ SG_ 2332421778 M2P_TMSCalibration_02 "水冷机组ID标定量";
CM_ SG_ 2332421778 M2P_IsoDetfunctionStatus_02 "绝缘检测功能状态";
CM_ SG_ 2332421778 M2P_TMS_Address_infor_02 "水冷机组编号";
CM_ SG_ 2332421779 M2P_SysMaxTemp_03 "MBMU电芯最高温度";
CM_ SG_ 2332421779 M2P_SysMinTemp_03 "MBMU电芯最低温度";
CM_ SG_ 2332421779 M2P_SysAvgTemp_03 "MBMU电芯平均温度";
CM_ SG_ 2332421779 M2P_PermitMaxVolt_03 "最高允许充电电压 （配置量）";
CM_ SG_ 2332421779 M2P_PermitMinVolt_03 "最低允许放电电压 （配置量）";
CM_ SG_ 2332421779 M2P_TMSCalibration_03 "水冷机组ID标定量";
CM_ SG_ 2332421779 M2P_IsoDetfunctionStatus_03 "绝缘检测功能状态";
CM_ SG_ 2332421779 M2P_TMS_Address_infor_03 "水冷机组编号";
CM_ SG_ 2332421780 M2P_SysMaxTemp_04 "MBMU电芯最高温度";
CM_ SG_ 2332421780 M2P_SysMinTemp_04 "MBMU电芯最低温度";
CM_ SG_ 2332421780 M2P_SysAvgTemp_04 "MBMU电芯平均温度";
CM_ SG_ 2332421780 M2P_PermitMaxVolt_04 "最高允许充电电压 （配置量）";
CM_ SG_ 2332421780 M2P_PermitMinVolt_04 "最低允许放电电压 （配置量）";
CM_ SG_ 2332421780 M2P_TMSCalibration_04 "水冷机组ID标定量";
CM_ SG_ 2332421780 M2P_IsoDetfunctionStatus_04 "绝缘检测功能状态";
CM_ SG_ 2332421780 M2P_TMS_Address_infor_04 "水冷机组编号";
CM_ SG_ 2332421781 M2P_SysMaxTemp_05 "MBMU电芯最高温度";
CM_ SG_ 2332421781 M2P_SysMinTemp_05 "MBMU电芯最低温度";
CM_ SG_ 2332421781 M2P_SysAvgTemp_05 "MBMU电芯平均温度";
CM_ SG_ 2332421781 M2P_PermitMaxVolt_05 "最高允许充电电压 （配置量）";
CM_ SG_ 2332421781 M2P_PermitMinVolt_05 "最低允许放电电压 （配置量）";
CM_ SG_ 2332421781 M2P_TMSCalibration_05 "水冷机组ID标定量";
CM_ SG_ 2332421781 M2P_IsoDetfunctionStatus_05 "绝缘检测功能状态";
CM_ SG_ 2332421781 M2P_TMS_Address_infor_05 "水冷机组编号";
CM_ SG_ 2332421782 M2P_SysMaxTemp_06 "MBMU电芯最高温度";
CM_ SG_ 2332421782 M2P_SysMinTemp_06 "MBMU电芯最低温度";
CM_ SG_ 2332421782 M2P_SysAvgTemp_06 "MBMU电芯平均温度";
CM_ SG_ 2332421782 M2P_PermitMaxVolt_06 "最高允许充电电压 （配置量）";
CM_ SG_ 2332421782 M2P_PermitMinVolt_06 "最低允许放电电压 （配置量）";
CM_ SG_ 2332421782 M2P_TMSCalibration_06 "水冷机组ID标定量";
CM_ SG_ 2332421782 M2P_IsoDetfunctionStatus_06 "绝缘检测功能状态";
CM_ SG_ 2332421782 M2P_TMS_Address_infor_06 "水冷机组编号";
CM_ SG_ 2332421783 M2P_SysMaxTemp_07 "MBMU电芯最高温度";
CM_ SG_ 2332421783 M2P_SysMinTemp_07 "MBMU电芯最低温度";
CM_ SG_ 2332421783 M2P_SysAvgTemp_07 "MBMU电芯平均温度";
CM_ SG_ 2332421783 M2P_PermitMaxVolt_07 "最高允许充电电压 （配置量）";
CM_ SG_ 2332421783 M2P_PermitMinVolt_07 "最低允许放电电压 （配置量）";
CM_ SG_ 2332421783 M2P_TMSCalibration_07 "水冷机组ID标定量";
CM_ SG_ 2332421783 M2P_IsoDetfunctionStatus_07 "绝缘检测功能状态";
CM_ SG_ 2332421783 M2P_TMS_Address_infor_07 "水冷机组编号";
CM_ SG_ 2332421784 M2P_SysMaxTemp_08 "MBMU电芯最高温度";
CM_ SG_ 2332421784 M2P_SysMinTemp_08 "MBMU电芯最低温度";
CM_ SG_ 2332421784 M2P_SysAvgTemp_08 "MBMU电芯平均温度";
CM_ SG_ 2332421784 M2P_PermitMaxVolt_08 "最高允许充电电压 （配置量）";
CM_ SG_ 2332421784 M2P_PermitMinVolt_08 "最低允许放电电压 （配置量）";
CM_ SG_ 2332421784 M2P_TMSCalibration_08 "水冷机组ID标定量";
CM_ SG_ 2332421784 M2P_IsoDetfunctionStatus_08 "绝缘检测功能状态";
CM_ SG_ 2332421784 M2P_TMS_Address_infor_08 "水冷机组编号";
CM_ SG_ 2332421785 M2P_SysMaxTemp_09 "MBMU电芯最高温度";
CM_ SG_ 2332421785 M2P_SysMinTemp_09 "MBMU电芯最低温度";
CM_ SG_ 2332421785 M2P_SysAvgTemp_09 "MBMU电芯平均温度";
CM_ SG_ 2332421785 M2P_PermitMaxVolt_09 "最高允许充电电压 （配置量）";
CM_ SG_ 2332421785 M2P_PermitMinVolt_09 "最低允许放电电压 （配置量）";
CM_ SG_ 2332421785 M2P_TMSCalibration_09 "水冷机组ID标定量";
CM_ SG_ 2332421785 M2P_IsoDetfunctionStatus_09 "绝缘检测功能状态";
CM_ SG_ 2332421785 M2P_TMS_Address_infor_09 "水冷机组编号";
CM_ SG_ 2332421786 M2P_SysMaxTemp_10 "MBMU电芯最高温度";
CM_ SG_ 2332421786 M2P_SysMinTemp_10 "MBMU电芯最低温度";
CM_ SG_ 2332421786 M2P_SysAvgTemp_10 "MBMU电芯平均温度";
CM_ SG_ 2332421786 M2P_PermitMaxVolt_10 "最高允许充电电压 （配置量）";
CM_ SG_ 2332421786 M2P_PermitMinVolt_10 "最低允许放电电压 （配置量）";
CM_ SG_ 2332421786 M2P_TMSCalibration_10 "水冷机组ID标定量";
CM_ SG_ 2332421786 M2P_IsoDetfunctionStatus_10 "绝缘检测功能状态";
CM_ SG_ 2332421786 M2P_TMS_Address_infor_10 "水冷机组编号";
CM_ SG_ 2332421787 M2P_SysMaxTemp_11 "MBMU电芯最高温度";
CM_ SG_ 2332421787 M2P_SysMinTemp_11 "MBMU电芯最低温度";
CM_ SG_ 2332421787 M2P_SysAvgTemp_11 "MBMU电芯平均温度";
CM_ SG_ 2332421787 M2P_PermitMaxVolt_11 "最高允许充电电压 （配置量）";
CM_ SG_ 2332421787 M2P_PermitMinVolt_11 "最低允许放电电压 （配置量）";
CM_ SG_ 2332421787 M2P_TMSCalibration_11 "水冷机组ID标定量";
CM_ SG_ 2332421787 M2P_IsoDetfunctionStatus_11 "绝缘检测功能状态";
CM_ SG_ 2332421787 M2P_TMS_Address_infor_11 "水冷机组编号";
CM_ SG_ 2332421788 M2P_SysMaxTemp_12 "MBMU电芯最高温度";
CM_ SG_ 2332421788 M2P_SysMinTemp_12 "MBMU电芯最低温度";
CM_ SG_ 2332421788 M2P_SysAvgTemp_12 "MBMU电芯平均温度";
CM_ SG_ 2332421788 M2P_PermitMaxVolt_12 "最高允许充电电压 （配置量）";
CM_ SG_ 2332421788 M2P_PermitMinVolt_12 "最低允许放电电压 （配置量）";
CM_ SG_ 2332421788 M2P_TMSCalibration_12 "水冷机组ID标定量";
CM_ SG_ 2332421788 M2P_IsoDetfunctionStatus_12 "绝缘检测功能状态";
CM_ SG_ 2332421788 M2P_TMS_Address_infor_12 "水冷机组编号";
CM_ SG_ 2332421789 M2P_SysMaxTemp_13 "MBMU电芯最高温度";
CM_ SG_ 2332421789 M2P_SysMinTemp_13 "MBMU电芯最低温度";
CM_ SG_ 2332421789 M2P_SysAvgTemp_13 "MBMU电芯平均温度";
CM_ SG_ 2332421789 M2P_PermitMaxVolt_13 "最高允许充电电压 （配置量）";
CM_ SG_ 2332421789 M2P_PermitMinVolt_13 "最低允许放电电压 （配置量）";
CM_ SG_ 2332421789 M2P_TMSCalibration_13 "水冷机组ID标定量";
CM_ SG_ 2332421789 M2P_IsoDetfunctionStatus_13 "绝缘检测功能状态";
CM_ SG_ 2332421789 M2P_TMS_Address_infor_13 "水冷机组编号";
CM_ SG_ 2332421790 M2P_SysMaxTemp_14 "MBMU电芯最高温度";
CM_ SG_ 2332421790 M2P_SysMinTemp_14 "MBMU电芯最低温度";
CM_ SG_ 2332421790 M2P_SysAvgTemp_14 "MBMU电芯平均温度";
CM_ SG_ 2332421790 M2P_PermitMaxVolt_14 "最高允许充电电压 （配置量）";
CM_ SG_ 2332421790 M2P_PermitMinVolt_14 "最低允许放电电压 （配置量）";
CM_ SG_ 2332421790 M2P_TMSCalibration_14 "水冷机组ID标定量";
CM_ SG_ 2332421790 M2P_IsoDetfunctionStatus_14 "绝缘检测功能状态";
CM_ SG_ 2332421790 M2P_TMS_Address_infor_14 "水冷机组编号";
CM_ SG_ 2332421791 M2P_SysMaxTemp_15 "MBMU电芯最高温度";
CM_ SG_ 2332421791 M2P_SysMinTemp_15 "MBMU电芯最低温度";
CM_ SG_ 2332421791 M2P_SysAvgTemp_15 "MBMU电芯平均温度";
CM_ SG_ 2332421791 M2P_PermitMaxVolt_15 "最高允许充电电压 （配置量）";
CM_ SG_ 2332421791 M2P_PermitMinVolt_15 "最低允许放电电压 （配置量）";
CM_ SG_ 2332421791 M2P_TMSCalibration_15 "水冷机组ID标定量";
CM_ SG_ 2332421791 M2P_IsoDetfunctionStatus_15 "绝缘检测功能状态";
CM_ SG_ 2332421791 M2P_TMS_Address_infor_15 "水冷机组编号";
CM_ SG_ 2332421792 M2P_SysMaxTemp_16 "MBMU电芯最高温度";
CM_ SG_ 2332421792 M2P_SysMinTemp_16 "MBMU电芯最低温度";
CM_ SG_ 2332421792 M2P_SysAvgTemp_16 "MBMU电芯平均温度";
CM_ SG_ 2332421792 M2P_PermitMaxVolt_16 "最高允许充电电压 （配置量）";
CM_ SG_ 2332421792 M2P_PermitMinVolt_16 "最低允许放电电压 （配置量）";
CM_ SG_ 2332421792 M2P_TMSCalibration_16 "水冷机组ID标定量";
CM_ SG_ 2332421792 M2P_IsoDetfunctionStatus_16 "绝缘检测功能状态";
CM_ SG_ 2332421792 M2P_TMS_Address_infor_16 "水冷机组编号";
CM_ SG_ 2332421793 M2P_SysMaxTemp_17 "MBMU电芯最高温度";
CM_ SG_ 2332421793 M2P_SysMinTemp_17 "MBMU电芯最低温度";
CM_ SG_ 2332421793 M2P_SysAvgTemp_17 "MBMU电芯平均温度";
CM_ SG_ 2332421793 M2P_PermitMaxVolt_17 "最高允许充电电压 （配置量）";
CM_ SG_ 2332421793 M2P_PermitMinVolt_17 "最低允许放电电压 （配置量）";
CM_ SG_ 2332421793 M2P_TMSCalibration_17 "水冷机组ID标定量";
CM_ SG_ 2332421793 M2P_IsoDetfunctionStatus_17 "绝缘检测功能状态";
CM_ SG_ 2332421793 M2P_TMS_Address_infor_17 "水冷机组编号";
CM_ SG_ 2332421794 M2P_SysMaxTemp_18 "MBMU电芯最高温度";
CM_ SG_ 2332421794 M2P_SysMinTemp_18 "MBMU电芯最低温度";
CM_ SG_ 2332421794 M2P_SysAvgTemp_18 "MBMU电芯平均温度";
CM_ SG_ 2332421794 M2P_PermitMaxVolt_18 "最高允许充电电压 （配置量）";
CM_ SG_ 2332421794 M2P_PermitMinVolt_18 "最低允许放电电压 （配置量）";
CM_ SG_ 2332421794 M2P_TMSCalibration_18 "水冷机组ID标定量";
CM_ SG_ 2332421794 M2P_IsoDetfunctionStatus_18 "绝缘检测功能状态";
CM_ SG_ 2332421794 M2P_TMS_Address_infor_18 "水冷机组编号";
CM_ SG_ 2332421795 M2P_SysMaxTemp_19 "MBMU电芯最高温度";
CM_ SG_ 2332421795 M2P_SysMinTemp_19 "MBMU电芯最低温度";
CM_ SG_ 2332421795 M2P_SysAvgTemp_19 "MBMU电芯平均温度";
CM_ SG_ 2332421795 M2P_PermitMaxVolt_19 "最高允许充电电压 （配置量）";
CM_ SG_ 2332421795 M2P_PermitMinVolt_19 "最低允许放电电压 （配置量）";
CM_ SG_ 2332421795 M2P_TMSCalibration_19 "水冷机组ID标定量";
CM_ SG_ 2332421795 M2P_IsoDetfunctionStatus_19 "绝缘检测功能状态";
CM_ SG_ 2332421795 M2P_TMS_Address_infor_19 "水冷机组编号";
CM_ SG_ 2332421796 M2P_SysMaxTemp_20 "MBMU电芯最高温度";
CM_ SG_ 2332421796 M2P_SysMinTemp_20 "MBMU电芯最低温度";
CM_ SG_ 2332421796 M2P_SysAvgTemp_20 "MBMU电芯平均温度";
CM_ SG_ 2332421796 M2P_PermitMaxVolt_20 "最高允许充电电压 （配置量）";
CM_ SG_ 2332421796 M2P_PermitMinVolt_20 "最低允许放电电压 （配置量）";
CM_ SG_ 2332421796 M2P_TMSCalibration_20 "水冷机组ID标定量";
CM_ SG_ 2332421796 M2P_IsoDetfunctionStatus_20 "绝缘检测功能状态";
CM_ SG_ 2332421796 M2P_TMS_Address_infor_20 "水冷机组编号";
CM_ SG_ 2332421797 M2P_SysMaxTemp_21 "MBMU电芯最高温度";
CM_ SG_ 2332421797 M2P_SysMinTemp_21 "MBMU电芯最低温度";
CM_ SG_ 2332421797 M2P_SysAvgTemp_21 "MBMU电芯平均温度";
CM_ SG_ 2332421797 M2P_PermitMaxVolt_21 "最高允许充电电压 （配置量）";
CM_ SG_ 2332421797 M2P_PermitMinVolt_21 "最低允许放电电压 （配置量）";
CM_ SG_ 2332421797 M2P_TMSCalibration_21 "水冷机组ID标定量";
CM_ SG_ 2332421797 M2P_IsoDetfunctionStatus_21 "绝缘检测功能状态";
CM_ SG_ 2332421797 M2P_TMS_Address_infor_21 "水冷机组编号";
CM_ SG_ 2332421798 M2P_SysMaxTemp_22 "MBMU电芯最高温度";
CM_ SG_ 2332421798 M2P_SysMinTemp_22 "MBMU电芯最低温度";
CM_ SG_ 2332421798 M2P_SysAvgTemp_22 "MBMU电芯平均温度";
CM_ SG_ 2332421798 M2P_PermitMaxVolt_22 "最高允许充电电压 （配置量）";
CM_ SG_ 2332421798 M2P_PermitMinVolt_22 "最低允许放电电压 （配置量）";
CM_ SG_ 2332421798 M2P_TMSCalibration_22 "水冷机组ID标定量";
CM_ SG_ 2332421798 M2P_IsoDetfunctionStatus_22 "绝缘检测功能状态";
CM_ SG_ 2332421798 M2P_TMS_Address_infor_22 "水冷机组编号";
CM_ SG_ 2332421799 M2P_SysMaxTemp_23 "MBMU电芯最高温度";
CM_ SG_ 2332421799 M2P_SysMinTemp_23 "MBMU电芯最低温度";
CM_ SG_ 2332421799 M2P_SysAvgTemp_23 "MBMU电芯平均温度";
CM_ SG_ 2332421799 M2P_PermitMaxVolt_23 "最高允许充电电压 （配置量）";
CM_ SG_ 2332421799 M2P_PermitMinVolt_23 "最低允许放电电压 （配置量）";
CM_ SG_ 2332421799 M2P_TMSCalibration_23 "水冷机组ID标定量";
CM_ SG_ 2332421799 M2P_IsoDetfunctionStatus_23 "绝缘检测功能状态";
CM_ SG_ 2332421799 M2P_TMS_Address_infor_23 "水冷机组编号";
CM_ SG_ 2332421800 M2P_SysMaxTemp_24 "MBMU电芯最高温度";
CM_ SG_ 2332421800 M2P_SysMinTemp_24 "MBMU电芯最低温度";
CM_ SG_ 2332421800 M2P_SysAvgTemp_24 "MBMU电芯平均温度";
CM_ SG_ 2332421800 M2P_PermitMaxVolt_24 "最高允许充电电压 （配置量）";
CM_ SG_ 2332421800 M2P_PermitMinVolt_24 "最低允许放电电压 （配置量）";
CM_ SG_ 2332421800 M2P_TMSCalibration_24 "水冷机组ID标定量";
CM_ SG_ 2332421800 M2P_IsoDetfunctionStatus_24 "绝缘检测功能状态";
CM_ SG_ 2332421800 M2P_TMS_Address_infor_24 "水冷机组编号";
CM_ SG_ 2332421801 M2P_SysMaxTemp_25 "MBMU电芯最高温度";
CM_ SG_ 2332421801 M2P_SysMinTemp_25 "MBMU电芯最低温度";
CM_ SG_ 2332421801 M2P_SysAvgTemp_25 "MBMU电芯平均温度";
CM_ SG_ 2332421801 M2P_PermitMaxVolt_25 "最高允许充电电压 （配置量）";
CM_ SG_ 2332421801 M2P_PermitMinVolt_25 "最低允许放电电压 （配置量）";
CM_ SG_ 2332421801 M2P_TMSCalibration_25 "水冷机组ID标定量";
CM_ SG_ 2332421801 M2P_IsoDetfunctionStatus_25 "绝缘检测功能状态";
CM_ SG_ 2332421801 M2P_TMS_Address_infor_25 "水冷机组编号";
CM_ SG_ 2332421802 M2P_SysMaxTemp_26 "MBMU电芯最高温度";
CM_ SG_ 2332421802 M2P_SysMinTemp_26 "MBMU电芯最低温度";
CM_ SG_ 2332421802 M2P_SysAvgTemp_26 "MBMU电芯平均温度";
CM_ SG_ 2332421802 M2P_PermitMaxVolt_26 "最高允许充电电压 （配置量）";
CM_ SG_ 2332421802 M2P_PermitMinVolt_26 "最低允许放电电压 （配置量）";
CM_ SG_ 2332421802 M2P_TMSCalibration_26 "水冷机组ID标定量";
CM_ SG_ 2332421802 M2P_IsoDetfunctionStatus_26 "绝缘检测功能状态";
CM_ SG_ 2332421802 M2P_TMS_Address_infor_26 "水冷机组编号";
CM_ SG_ 2332421803 M2P_SysMaxTemp_27 "MBMU电芯最高温度";
CM_ SG_ 2332421803 M2P_SysMinTemp_27 "MBMU电芯最低温度";
CM_ SG_ 2332421803 M2P_SysAvgTemp_27 "MBMU电芯平均温度";
CM_ SG_ 2332421803 M2P_PermitMaxVolt_27 "最高允许充电电压 （配置量）";
CM_ SG_ 2332421803 M2P_PermitMinVolt_27 "最低允许放电电压 （配置量）";
CM_ SG_ 2332421803 M2P_TMSCalibration_27 "水冷机组ID标定量";
CM_ SG_ 2332421803 M2P_IsoDetfunctionStatus_27 "绝缘检测功能状态";
CM_ SG_ 2332421803 M2P_TMS_Address_infor_27 "水冷机组编号";
CM_ SG_ 2332421804 M2P_SysMaxTemp_28 "MBMU电芯最高温度";
CM_ SG_ 2332421804 M2P_SysMinTemp_28 "MBMU电芯最低温度";
CM_ SG_ 2332421804 M2P_SysAvgTemp_28 "MBMU电芯平均温度";
CM_ SG_ 2332421804 M2P_PermitMaxVolt_28 "最高允许充电电压 （配置量）";
CM_ SG_ 2332421804 M2P_PermitMinVolt_28 "最低允许放电电压 （配置量）";
CM_ SG_ 2332421804 M2P_TMSCalibration_28 "水冷机组ID标定量";
CM_ SG_ 2332421804 M2P_IsoDetfunctionStatus_28 "绝缘检测功能状态";
CM_ SG_ 2332421804 M2P_TMS_Address_infor_28 "水冷机组编号";
CM_ SG_ 2332421805 M2P_SysMaxTemp_29 "MBMU电芯最高温度";
CM_ SG_ 2332421805 M2P_SysMinTemp_29 "MBMU电芯最低温度";
CM_ SG_ 2332421805 M2P_SysAvgTemp_29 "MBMU电芯平均温度";
CM_ SG_ 2332421805 M2P_PermitMaxVolt_29 "最高允许充电电压 （配置量）";
CM_ SG_ 2332421805 M2P_PermitMinVolt_29 "最低允许放电电压 （配置量）";
CM_ SG_ 2332421805 M2P_TMSCalibration_29 "水冷机组ID标定量";
CM_ SG_ 2332421805 M2P_IsoDetfunctionStatus_29 "绝缘检测功能状态";
CM_ SG_ 2332421805 M2P_TMS_Address_infor_29 "水冷机组编号";
CM_ SG_ 2332421806 M2P_SysMaxTemp_30 "MBMU电芯最高温度";
CM_ SG_ 2332421806 M2P_SysMinTemp_30 "MBMU电芯最低温度";
CM_ SG_ 2332421806 M2P_SysAvgTemp_30 "MBMU电芯平均温度";
CM_ SG_ 2332421806 M2P_PermitMaxVolt_30 "最高允许充电电压 （配置量）";
CM_ SG_ 2332421806 M2P_PermitMinVolt_30 "最低允许放电电压 （配置量）";
CM_ SG_ 2332421806 M2P_TMSCalibration_30 "水冷机组ID标定量";
CM_ SG_ 2332421806 M2P_IsoDetfunctionStatus_30 "绝缘检测功能状态";
CM_ SG_ 2332421806 M2P_TMS_Address_infor_30 "水冷机组编号";
CM_ SG_ 2332421807 M2P_SysMaxTemp_31 "MBMU电芯最高温度";
CM_ SG_ 2332421807 M2P_SysMinTemp_31 "MBMU电芯最低温度";
CM_ SG_ 2332421807 M2P_SysAvgTemp_31 "MBMU电芯平均温度";
CM_ SG_ 2332421807 M2P_PermitMaxVolt_31 "最高允许充电电压 （配置量）";
CM_ SG_ 2332421807 M2P_PermitMinVolt_31 "最低允许放电电压 （配置量）";
CM_ SG_ 2332421807 M2P_TMSCalibration_31 "水冷机组ID标定量";
CM_ SG_ 2332421807 M2P_IsoDetfunctionStatus_31 "绝缘检测功能状态";
CM_ SG_ 2332421807 M2P_TMS_Address_infor_31 "水冷机组编号";
CM_ SG_ 2332487313 M2P_PermitMaxPower_Charge_01 "系统最大允许充电功率";
CM_ SG_ 2332487313 M2P_PermitMaxPower_DisCharge_01 "系统最大允许放电功率";
CM_ SG_ 2332487313 M2P_Power_01 "系统实时功率";
CM_ SG_ 2332487313 M2P_StepChrMode_01 "系统Step-Charge模式";
CM_ SG_ 2332487313 M2P_BUS1_HVState_01 "汇流排1上高压状态                                    ";
CM_ SG_ 2332487313 M2P_BUS2_HVState_01 "汇流排2上高压状态                                    ";
CM_ SG_ 2332487313 M2P_BUS3_HVState_01 "汇流排3上高压状态                                    ";
CM_ SG_ 2332487313 M2P_BUS4_HVState_01 "汇流排4上高压状态                                    ";
CM_ SG_ 2332487313 M2P_BUS5_HVState_01 "汇流排5上高压状态                                    ";
CM_ SG_ 2332487313 M2P_BUS6_HVState_01 "汇流排6上高压状态                                    ";
CM_ SG_ 2332487313 M2P_BUS7_HVState_01 "汇流排7上高压状态                                    ";
CM_ SG_ 2332487313 M2P_BUS8_HVState_01 "汇流排8上高压状态                                    ";
CM_ SG_ 2332487313 M2P_BUS9_HVState_01 "汇流排9上高压状态                                    ";
CM_ SG_ 2332487313 M2P_BUS10_HVState_01 "汇流排10上高压状态                                    ";
CM_ SG_ 2332487313 M2P_BUS11_HVState_01 "汇流排11上高压状态                                    ";
CM_ SG_ 2332487313 M2P_BUS12_HVState_01 "汇流排12上高压状态                                    ";
CM_ SG_ 2332487314 M2P_PermitMaxPower_Charge_02 "系统最大允许充电功率";
CM_ SG_ 2332487314 M2P_PermitMaxPower_DisCharge_02 "系统最大允许放电功率";
CM_ SG_ 2332487314 M2P_Power_02 "系统实时功率";
CM_ SG_ 2332487314 M2P_StepChrMode_02 "系统Step-Charge模式";
CM_ SG_ 2332487314 M2P_BUS1_HVState_02 "汇流排1上高压状态                                    ";
CM_ SG_ 2332487314 M2P_BUS2_HVState_02 "汇流排2上高压状态                                    ";
CM_ SG_ 2332487314 M2P_BUS3_HVState_02 "汇流排3上高压状态                                    ";
CM_ SG_ 2332487314 M2P_BUS4_HVState_02 "汇流排4上高压状态                                    ";
CM_ SG_ 2332487314 M2P_BUS5_HVState_02 "汇流排5上高压状态                                    ";
CM_ SG_ 2332487314 M2P_BUS6_HVState_02 "汇流排6上高压状态                                    ";
CM_ SG_ 2332487314 M2P_BUS7_HVState_02 "汇流排7上高压状态                                    ";
CM_ SG_ 2332487314 M2P_BUS8_HVState_02 "汇流排8上高压状态                                    ";
CM_ SG_ 2332487314 M2P_BUS9_HVState_02 "汇流排9上高压状态                                    ";
CM_ SG_ 2332487314 M2P_BUS10_HVState_02 "汇流排10上高压状态                                    ";
CM_ SG_ 2332487314 M2P_BUS11_HVState_02 "汇流排11上高压状态                                    ";
CM_ SG_ 2332487314 M2P_BUS12_HVState_02 "汇流排12上高压状态                                    ";
CM_ SG_ 2332487315 M2P_PermitMaxPower_Charge_03 "系统最大允许充电功率";
CM_ SG_ 2332487315 M2P_PermitMaxPower_DisCharge_03 "系统最大允许放电功率";
CM_ SG_ 2332487315 M2P_Power_03 "系统实时功率";
CM_ SG_ 2332487315 M2P_StepChrMode_03 "系统Step-Charge模式";
CM_ SG_ 2332487315 M2P_BUS1_HVState_03 "汇流排1上高压状态                                    ";
CM_ SG_ 2332487315 M2P_BUS2_HVState_03 "汇流排2上高压状态                                    ";
CM_ SG_ 2332487315 M2P_BUS3_HVState_03 "汇流排3上高压状态                                    ";
CM_ SG_ 2332487315 M2P_BUS4_HVState_03 "汇流排4上高压状态                                    ";
CM_ SG_ 2332487315 M2P_BUS5_HVState_03 "汇流排5上高压状态                                    ";
CM_ SG_ 2332487315 M2P_BUS6_HVState_03 "汇流排6上高压状态                                    ";
CM_ SG_ 2332487315 M2P_BUS7_HVState_03 "汇流排7上高压状态                                    ";
CM_ SG_ 2332487315 M2P_BUS8_HVState_03 "汇流排8上高压状态                                    ";
CM_ SG_ 2332487315 M2P_BUS9_HVState_03 "汇流排9上高压状态                                    ";
CM_ SG_ 2332487315 M2P_BUS10_HVState_03 "汇流排10上高压状态                                    ";
CM_ SG_ 2332487315 M2P_BUS11_HVState_03 "汇流排11上高压状态                                    ";
CM_ SG_ 2332487315 M2P_BUS12_HVState_03 "汇流排12上高压状态                                    ";
CM_ SG_ 2332487316 M2P_PermitMaxPower_Charge_04 "系统最大允许充电功率";
CM_ SG_ 2332487316 M2P_PermitMaxPower_DisCharge_04 "系统最大允许放电功率";
CM_ SG_ 2332487316 M2P_Power_04 "系统实时功率";
CM_ SG_ 2332487316 M2P_StepChrMode_04 "系统Step-Charge模式";
CM_ SG_ 2332487316 M2P_BUS1_HVState_04 "汇流排1上高压状态                                    ";
CM_ SG_ 2332487316 M2P_BUS2_HVState_04 "汇流排2上高压状态                                    ";
CM_ SG_ 2332487316 M2P_BUS3_HVState_04 "汇流排3上高压状态                                    ";
CM_ SG_ 2332487316 M2P_BUS4_HVState_04 "汇流排4上高压状态                                    ";
CM_ SG_ 2332487316 M2P_BUS5_HVState_04 "汇流排5上高压状态                                    ";
CM_ SG_ 2332487316 M2P_BUS6_HVState_04 "汇流排6上高压状态                                    ";
CM_ SG_ 2332487316 M2P_BUS7_HVState_04 "汇流排7上高压状态                                    ";
CM_ SG_ 2332487316 M2P_BUS8_HVState_04 "汇流排8上高压状态                                    ";
CM_ SG_ 2332487316 M2P_BUS9_HVState_04 "汇流排9上高压状态                                    ";
CM_ SG_ 2332487316 M2P_BUS10_HVState_04 "汇流排10上高压状态                                    ";
CM_ SG_ 2332487316 M2P_BUS11_HVState_04 "汇流排11上高压状态                                    ";
CM_ SG_ 2332487316 M2P_BUS12_HVState_04 "汇流排12上高压状态                                    ";
CM_ SG_ 2332487317 M2P_PermitMaxPower_Charge_05 "系统最大允许充电功率";
CM_ SG_ 2332487317 M2P_PermitMaxPower_DisCharge_05 "系统最大允许放电功率";
CM_ SG_ 2332487317 M2P_Power_05 "系统实时功率";
CM_ SG_ 2332487317 M2P_StepChrMode_05 "系统Step-Charge模式";
CM_ SG_ 2332487317 M2P_BUS1_HVState_05 "汇流排1上高压状态                                    ";
CM_ SG_ 2332487317 M2P_BUS2_HVState_05 "汇流排2上高压状态                                    ";
CM_ SG_ 2332487317 M2P_BUS3_HVState_05 "汇流排3上高压状态                                    ";
CM_ SG_ 2332487317 M2P_BUS4_HVState_05 "汇流排4上高压状态                                    ";
CM_ SG_ 2332487317 M2P_BUS5_HVState_05 "汇流排5上高压状态                                    ";
CM_ SG_ 2332487317 M2P_BUS6_HVState_05 "汇流排6上高压状态                                    ";
CM_ SG_ 2332487317 M2P_BUS7_HVState_05 "汇流排7上高压状态                                    ";
CM_ SG_ 2332487317 M2P_BUS8_HVState_05 "汇流排8上高压状态                                    ";
CM_ SG_ 2332487317 M2P_BUS9_HVState_05 "汇流排9上高压状态                                    ";
CM_ SG_ 2332487317 M2P_BUS10_HVState_05 "汇流排10上高压状态                                    ";
CM_ SG_ 2332487317 M2P_BUS11_HVState_05 "汇流排11上高压状态                                    ";
CM_ SG_ 2332487317 M2P_BUS12_HVState_05 "汇流排12上高压状态                                    ";
CM_ SG_ 2332487318 M2P_PermitMaxPower_Charge_06 "系统最大允许充电功率";
CM_ SG_ 2332487318 M2P_PermitMaxPower_DisCharge_06 "系统最大允许放电功率";
CM_ SG_ 2332487318 M2P_Power_06 "系统实时功率";
CM_ SG_ 2332487318 M2P_StepChrMode_06 "系统Step-Charge模式";
CM_ SG_ 2332487318 M2P_BUS1_HVState_06 "汇流排1上高压状态                                    ";
CM_ SG_ 2332487318 M2P_BUS2_HVState_06 "汇流排2上高压状态                                    ";
CM_ SG_ 2332487318 M2P_BUS3_HVState_06 "汇流排3上高压状态                                    ";
CM_ SG_ 2332487318 M2P_BUS4_HVState_06 "汇流排4上高压状态                                    ";
CM_ SG_ 2332487318 M2P_BUS5_HVState_06 "汇流排5上高压状态                                    ";
CM_ SG_ 2332487318 M2P_BUS6_HVState_06 "汇流排6上高压状态                                    ";
CM_ SG_ 2332487318 M2P_BUS7_HVState_06 "汇流排7上高压状态                                    ";
CM_ SG_ 2332487318 M2P_BUS8_HVState_06 "汇流排8上高压状态                                    ";
CM_ SG_ 2332487318 M2P_BUS9_HVState_06 "汇流排9上高压状态                                    ";
CM_ SG_ 2332487318 M2P_BUS10_HVState_06 "汇流排10上高压状态                                    ";
CM_ SG_ 2332487318 M2P_BUS11_HVState_06 "汇流排11上高压状态                                    ";
CM_ SG_ 2332487318 M2P_BUS12_HVState_06 "汇流排12上高压状态                                    ";
CM_ SG_ 2332487319 M2P_PermitMaxPower_Charge_07 "系统最大允许充电功率";
CM_ SG_ 2332487319 M2P_PermitMaxPower_DisCharge_07 "系统最大允许放电功率";
CM_ SG_ 2332487319 M2P_Power_07 "系统实时功率";
CM_ SG_ 2332487319 M2P_StepChrMode_07 "系统Step-Charge模式";
CM_ SG_ 2332487319 M2P_BUS1_HVState_07 "汇流排1上高压状态                                    ";
CM_ SG_ 2332487319 M2P_BUS2_HVState_07 "汇流排2上高压状态                                    ";
CM_ SG_ 2332487319 M2P_BUS3_HVState_07 "汇流排3上高压状态                                    ";
CM_ SG_ 2332487319 M2P_BUS4_HVState_07 "汇流排4上高压状态                                    ";
CM_ SG_ 2332487319 M2P_BUS5_HVState_07 "汇流排5上高压状态                                    ";
CM_ SG_ 2332487319 M2P_BUS6_HVState_07 "汇流排6上高压状态                                    ";
CM_ SG_ 2332487319 M2P_BUS7_HVState_07 "汇流排7上高压状态                                    ";
CM_ SG_ 2332487319 M2P_BUS8_HVState_07 "汇流排8上高压状态                                    ";
CM_ SG_ 2332487319 M2P_BUS9_HVState_07 "汇流排9上高压状态                                    ";
CM_ SG_ 2332487319 M2P_BUS10_HVState_07 "汇流排10上高压状态                                    ";
CM_ SG_ 2332487319 M2P_BUS11_HVState_07 "汇流排11上高压状态                                    ";
CM_ SG_ 2332487319 M2P_BUS12_HVState_07 "汇流排12上高压状态                                    ";
CM_ SG_ 2332487320 M2P_PermitMaxPower_Charge_08 "系统最大允许充电功率";
CM_ SG_ 2332487320 M2P_PermitMaxPower_DisCharge_08 "系统最大允许放电功率";
CM_ SG_ 2332487320 M2P_Power_08 "系统实时功率";
CM_ SG_ 2332487320 M2P_StepChrMode_08 "系统Step-Charge模式";
CM_ SG_ 2332487320 M2P_BUS1_HVState_08 "汇流排1上高压状态                                    ";
CM_ SG_ 2332487320 M2P_BUS2_HVState_08 "汇流排2上高压状态                                    ";
CM_ SG_ 2332487320 M2P_BUS3_HVState_08 "汇流排3上高压状态                                    ";
CM_ SG_ 2332487320 M2P_BUS4_HVState_08 "汇流排4上高压状态                                    ";
CM_ SG_ 2332487320 M2P_BUS5_HVState_08 "汇流排5上高压状态                                    ";
CM_ SG_ 2332487320 M2P_BUS6_HVState_08 "汇流排6上高压状态                                    ";
CM_ SG_ 2332487320 M2P_BUS7_HVState_08 "汇流排7上高压状态                                    ";
CM_ SG_ 2332487320 M2P_BUS8_HVState_08 "汇流排8上高压状态                                    ";
CM_ SG_ 2332487320 M2P_BUS9_HVState_08 "汇流排9上高压状态                                    ";
CM_ SG_ 2332487320 M2P_BUS10_HVState_08 "汇流排10上高压状态                                    ";
CM_ SG_ 2332487320 M2P_BUS11_HVState_08 "汇流排11上高压状态                                    ";
CM_ SG_ 2332487320 M2P_BUS12_HVState_08 "汇流排12上高压状态                                    ";
CM_ SG_ 2332487321 M2P_PermitMaxPower_Charge_09 "系统最大允许充电功率";
CM_ SG_ 2332487321 M2P_PermitMaxPower_DisCharge_09 "系统最大允许放电功率";
CM_ SG_ 2332487321 M2P_Power_09 "系统实时功率";
CM_ SG_ 2332487321 M2P_StepChrMode_09 "系统Step-Charge模式";
CM_ SG_ 2332487321 M2P_BUS1_HVState_09 "汇流排1上高压状态                                    ";
CM_ SG_ 2332487321 M2P_BUS2_HVState_09 "汇流排2上高压状态                                    ";
CM_ SG_ 2332487321 M2P_BUS3_HVState_09 "汇流排3上高压状态                                    ";
CM_ SG_ 2332487321 M2P_BUS4_HVState_09 "汇流排4上高压状态                                    ";
CM_ SG_ 2332487321 M2P_BUS5_HVState_09 "汇流排5上高压状态                                    ";
CM_ SG_ 2332487321 M2P_BUS6_HVState_09 "汇流排6上高压状态                                    ";
CM_ SG_ 2332487321 M2P_BUS7_HVState_09 "汇流排7上高压状态                                    ";
CM_ SG_ 2332487321 M2P_BUS8_HVState_09 "汇流排8上高压状态                                    ";
CM_ SG_ 2332487321 M2P_BUS9_HVState_09 "汇流排9上高压状态                                    ";
CM_ SG_ 2332487321 M2P_BUS10_HVState_09 "汇流排10上高压状态                                    ";
CM_ SG_ 2332487321 M2P_BUS11_HVState_09 "汇流排11上高压状态                                    ";
CM_ SG_ 2332487321 M2P_BUS12_HVState_09 "汇流排12上高压状态                                    ";
CM_ SG_ 2332487322 M2P_PermitMaxPower_Charge_10 "系统最大允许充电功率";
CM_ SG_ 2332487322 M2P_PermitMaxPower_DisCharge_10 "系统最大允许放电功率";
CM_ SG_ 2332487322 M2P_Power_10 "系统实时功率";
CM_ SG_ 2332487322 M2P_StepChrMode_10 "系统Step-Charge模式";
CM_ SG_ 2332487322 M2P_BUS1_HVState_10 "汇流排1上高压状态                                    ";
CM_ SG_ 2332487322 M2P_BUS2_HVState_10 "汇流排2上高压状态                                    ";
CM_ SG_ 2332487322 M2P_BUS3_HVState_10 "汇流排3上高压状态                                    ";
CM_ SG_ 2332487322 M2P_BUS4_HVState_10 "汇流排4上高压状态                                    ";
CM_ SG_ 2332487322 M2P_BUS5_HVState_10 "汇流排5上高压状态                                    ";
CM_ SG_ 2332487322 M2P_BUS6_HVState_10 "汇流排6上高压状态                                    ";
CM_ SG_ 2332487322 M2P_BUS7_HVState_10 "汇流排7上高压状态                                    ";
CM_ SG_ 2332487322 M2P_BUS8_HVState_10 "汇流排8上高压状态                                    ";
CM_ SG_ 2332487322 M2P_BUS9_HVState_10 "汇流排9上高压状态                                    ";
CM_ SG_ 2332487322 M2P_BUS10_HVState_10 "汇流排10上高压状态                                    ";
CM_ SG_ 2332487322 M2P_BUS11_HVState_10 "汇流排11上高压状态                                    ";
CM_ SG_ 2332487322 M2P_BUS12_HVState_10 "汇流排12上高压状态                                    ";
CM_ SG_ 2332487323 M2P_PermitMaxPower_Charge_11 "系统最大允许充电功率";
CM_ SG_ 2332487323 M2P_PermitMaxPower_DisCharge_11 "系统最大允许放电功率";
CM_ SG_ 2332487323 M2P_Power_11 "系统实时功率";
CM_ SG_ 2332487323 M2P_StepChrMode_11 "系统Step-Charge模式";
CM_ SG_ 2332487323 M2P_BUS1_HVState_11 "汇流排1上高压状态                                    ";
CM_ SG_ 2332487323 M2P_BUS2_HVState_11 "汇流排2上高压状态                                    ";
CM_ SG_ 2332487323 M2P_BUS3_HVState_11 "汇流排3上高压状态                                    ";
CM_ SG_ 2332487323 M2P_BUS4_HVState_11 "汇流排4上高压状态                                    ";
CM_ SG_ 2332487323 M2P_BUS5_HVState_11 "汇流排5上高压状态                                    ";
CM_ SG_ 2332487323 M2P_BUS6_HVState_11 "汇流排6上高压状态                                    ";
CM_ SG_ 2332487323 M2P_BUS7_HVState_11 "汇流排7上高压状态                                    ";
CM_ SG_ 2332487323 M2P_BUS8_HVState_11 "汇流排8上高压状态                                    ";
CM_ SG_ 2332487323 M2P_BUS9_HVState_11 "汇流排9上高压状态                                    ";
CM_ SG_ 2332487323 M2P_BUS10_HVState_11 "汇流排10上高压状态                                    ";
CM_ SG_ 2332487323 M2P_BUS11_HVState_11 "汇流排11上高压状态                                    ";
CM_ SG_ 2332487323 M2P_BUS12_HVState_11 "汇流排12上高压状态                                    ";
CM_ SG_ 2332487324 M2P_PermitMaxPower_Charge_12 "系统最大允许充电功率";
CM_ SG_ 2332487324 M2P_PermitMaxPower_DisCharge_12 "系统最大允许放电功率";
CM_ SG_ 2332487324 M2P_Power_12 "系统实时功率";
CM_ SG_ 2332487324 M2P_StepChrMode_12 "系统Step-Charge模式";
CM_ SG_ 2332487324 M2P_BUS1_HVState_12 "汇流排1上高压状态                                    ";
CM_ SG_ 2332487324 M2P_BUS2_HVState_12 "汇流排2上高压状态                                    ";
CM_ SG_ 2332487324 M2P_BUS3_HVState_12 "汇流排3上高压状态                                    ";
CM_ SG_ 2332487324 M2P_BUS4_HVState_12 "汇流排4上高压状态                                    ";
CM_ SG_ 2332487324 M2P_BUS5_HVState_12 "汇流排5上高压状态                                    ";
CM_ SG_ 2332487324 M2P_BUS6_HVState_12 "汇流排6上高压状态                                    ";
CM_ SG_ 2332487324 M2P_BUS7_HVState_12 "汇流排7上高压状态                                    ";
CM_ SG_ 2332487324 M2P_BUS8_HVState_12 "汇流排8上高压状态                                    ";
CM_ SG_ 2332487324 M2P_BUS9_HVState_12 "汇流排9上高压状态                                    ";
CM_ SG_ 2332487324 M2P_BUS10_HVState_12 "汇流排10上高压状态                                    ";
CM_ SG_ 2332487324 M2P_BUS11_HVState_12 "汇流排11上高压状态                                    ";
CM_ SG_ 2332487324 M2P_BUS12_HVState_12 "汇流排12上高压状态                                    ";
CM_ SG_ 2332487325 M2P_PermitMaxPower_Charge_13 "系统最大允许充电功率";
CM_ SG_ 2332487325 M2P_PermitMaxPower_DisCharge_13 "系统最大允许放电功率";
CM_ SG_ 2332487325 M2P_Power_13 "系统实时功率";
CM_ SG_ 2332487325 M2P_StepChrMode_13 "系统Step-Charge模式";
CM_ SG_ 2332487325 M2P_BUS1_HVState_13 "汇流排1上高压状态                                    ";
CM_ SG_ 2332487325 M2P_BUS2_HVState_13 "汇流排2上高压状态                                    ";
CM_ SG_ 2332487325 M2P_BUS3_HVState_13 "汇流排3上高压状态                                    ";
CM_ SG_ 2332487325 M2P_BUS4_HVState_13 "汇流排4上高压状态                                    ";
CM_ SG_ 2332487325 M2P_BUS5_HVState_13 "汇流排5上高压状态                                    ";
CM_ SG_ 2332487325 M2P_BUS6_HVState_13 "汇流排6上高压状态                                    ";
CM_ SG_ 2332487325 M2P_BUS7_HVState_13 "汇流排7上高压状态                                    ";
CM_ SG_ 2332487325 M2P_BUS8_HVState_13 "汇流排8上高压状态                                    ";
CM_ SG_ 2332487325 M2P_BUS9_HVState_13 "汇流排9上高压状态                                    ";
CM_ SG_ 2332487325 M2P_BUS10_HVState_13 "汇流排10上高压状态                                    ";
CM_ SG_ 2332487325 M2P_BUS11_HVState_13 "汇流排11上高压状态                                    ";
CM_ SG_ 2332487325 M2P_BUS12_HVState_13 "汇流排12上高压状态                                    ";
CM_ SG_ 2332487326 M2P_PermitMaxPower_Charge_14 "系统最大允许充电功率";
CM_ SG_ 2332487326 M2P_PermitMaxPower_DisCharge_14 "系统最大允许放电功率";
CM_ SG_ 2332487326 M2P_Power_14 "系统实时功率";
CM_ SG_ 2332487326 M2P_StepChrMode_14 "系统Step-Charge模式";
CM_ SG_ 2332487326 M2P_BUS1_HVState_14 "汇流排1上高压状态                                    ";
CM_ SG_ 2332487326 M2P_BUS2_HVState_14 "汇流排2上高压状态                                    ";
CM_ SG_ 2332487326 M2P_BUS3_HVState_14 "汇流排3上高压状态                                    ";
CM_ SG_ 2332487326 M2P_BUS4_HVState_14 "汇流排4上高压状态                                    ";
CM_ SG_ 2332487326 M2P_BUS5_HVState_14 "汇流排5上高压状态                                    ";
CM_ SG_ 2332487326 M2P_BUS6_HVState_14 "汇流排6上高压状态                                    ";
CM_ SG_ 2332487326 M2P_BUS7_HVState_14 "汇流排7上高压状态                                    ";
CM_ SG_ 2332487326 M2P_BUS8_HVState_14 "汇流排8上高压状态                                    ";
CM_ SG_ 2332487326 M2P_BUS9_HVState_14 "汇流排9上高压状态                                    ";
CM_ SG_ 2332487326 M2P_BUS10_HVState_14 "汇流排10上高压状态                                    ";
CM_ SG_ 2332487326 M2P_BUS11_HVState_14 "汇流排11上高压状态                                    ";
CM_ SG_ 2332487326 M2P_BUS12_HVState_14 "汇流排12上高压状态                                    ";
CM_ SG_ 2332487327 M2P_PermitMaxPower_Charge_15 "系统最大允许充电功率";
CM_ SG_ 2332487327 M2P_PermitMaxPower_DisCharge_15 "系统最大允许放电功率";
CM_ SG_ 2332487327 M2P_Power_15 "系统实时功率";
CM_ SG_ 2332487327 M2P_StepChrMode_15 "系统Step-Charge模式";
CM_ SG_ 2332487327 M2P_BUS1_HVState_15 "汇流排1上高压状态                                    ";
CM_ SG_ 2332487327 M2P_BUS2_HVState_15 "汇流排2上高压状态                                    ";
CM_ SG_ 2332487327 M2P_BUS3_HVState_15 "汇流排3上高压状态                                    ";
CM_ SG_ 2332487327 M2P_BUS4_HVState_15 "汇流排4上高压状态                                    ";
CM_ SG_ 2332487327 M2P_BUS5_HVState_15 "汇流排5上高压状态                                    ";
CM_ SG_ 2332487327 M2P_BUS6_HVState_15 "汇流排6上高压状态                                    ";
CM_ SG_ 2332487327 M2P_BUS7_HVState_15 "汇流排7上高压状态                                    ";
CM_ SG_ 2332487327 M2P_BUS8_HVState_15 "汇流排8上高压状态                                    ";
CM_ SG_ 2332487327 M2P_BUS9_HVState_15 "汇流排9上高压状态                                    ";
CM_ SG_ 2332487327 M2P_BUS10_HVState_15 "汇流排10上高压状态                                    ";
CM_ SG_ 2332487327 M2P_BUS11_HVState_15 "汇流排11上高压状态                                    ";
CM_ SG_ 2332487327 M2P_BUS12_HVState_15 "汇流排12上高压状态                                    ";
CM_ SG_ 2332487328 M2P_PermitMaxPower_Charge_16 "系统最大允许充电功率";
CM_ SG_ 2332487328 M2P_PermitMaxPower_DisCharge_16 "系统最大允许放电功率";
CM_ SG_ 2332487328 M2P_Power_16 "系统实时功率";
CM_ SG_ 2332487328 M2P_StepChrMode_16 "系统Step-Charge模式";
CM_ SG_ 2332487328 M2P_BUS1_HVState_16 "汇流排1上高压状态                                    ";
CM_ SG_ 2332487328 M2P_BUS2_HVState_16 "汇流排2上高压状态                                    ";
CM_ SG_ 2332487328 M2P_BUS3_HVState_16 "汇流排3上高压状态                                    ";
CM_ SG_ 2332487328 M2P_BUS4_HVState_16 "汇流排4上高压状态                                    ";
CM_ SG_ 2332487328 M2P_BUS5_HVState_16 "汇流排5上高压状态                                    ";
CM_ SG_ 2332487328 M2P_BUS6_HVState_16 "汇流排6上高压状态                                    ";
CM_ SG_ 2332487328 M2P_BUS7_HVState_16 "汇流排7上高压状态                                    ";
CM_ SG_ 2332487328 M2P_BUS8_HVState_16 "汇流排8上高压状态                                    ";
CM_ SG_ 2332487328 M2P_BUS9_HVState_16 "汇流排9上高压状态                                    ";
CM_ SG_ 2332487328 M2P_BUS10_HVState_16 "汇流排10上高压状态                                    ";
CM_ SG_ 2332487328 M2P_BUS11_HVState_16 "汇流排11上高压状态                                    ";
CM_ SG_ 2332487328 M2P_BUS12_HVState_16 "汇流排12上高压状态                                    ";
CM_ SG_ 2332487329 M2P_PermitMaxPower_Charge_17 "系统最大允许充电功率";
CM_ SG_ 2332487329 M2P_PermitMaxPower_DisCharge_17 "系统最大允许放电功率";
CM_ SG_ 2332487329 M2P_Power_17 "系统实时功率";
CM_ SG_ 2332487329 M2P_StepChrMode_17 "系统Step-Charge模式";
CM_ SG_ 2332487329 M2P_BUS1_HVState_17 "汇流排1上高压状态                                    ";
CM_ SG_ 2332487329 M2P_BUS2_HVState_17 "汇流排2上高压状态                                    ";
CM_ SG_ 2332487329 M2P_BUS3_HVState_17 "汇流排3上高压状态                                    ";
CM_ SG_ 2332487329 M2P_BUS4_HVState_17 "汇流排4上高压状态                                    ";
CM_ SG_ 2332487329 M2P_BUS5_HVState_17 "汇流排5上高压状态                                    ";
CM_ SG_ 2332487329 M2P_BUS6_HVState_17 "汇流排6上高压状态                                    ";
CM_ SG_ 2332487329 M2P_BUS7_HVState_17 "汇流排7上高压状态                                    ";
CM_ SG_ 2332487329 M2P_BUS8_HVState_17 "汇流排8上高压状态                                    ";
CM_ SG_ 2332487329 M2P_BUS9_HVState_17 "汇流排9上高压状态                                    ";
CM_ SG_ 2332487329 M2P_BUS10_HVState_17 "汇流排10上高压状态                                    ";
CM_ SG_ 2332487329 M2P_BUS11_HVState_17 "汇流排11上高压状态                                    ";
CM_ SG_ 2332487329 M2P_BUS12_HVState_17 "汇流排12上高压状态                                    ";
CM_ SG_ 2332487330 M2P_PermitMaxPower_Charge_18 "系统最大允许充电功率";
CM_ SG_ 2332487330 M2P_PermitMaxPower_DisCharge_18 "系统最大允许放电功率";
CM_ SG_ 2332487330 M2P_Power_18 "系统实时功率";
CM_ SG_ 2332487330 M2P_StepChrMode_18 "系统Step-Charge模式";
CM_ SG_ 2332487330 M2P_BUS1_HVState_18 "汇流排1上高压状态                                    ";
CM_ SG_ 2332487330 M2P_BUS2_HVState_18 "汇流排2上高压状态                                    ";
CM_ SG_ 2332487330 M2P_BUS3_HVState_18 "汇流排3上高压状态                                    ";
CM_ SG_ 2332487330 M2P_BUS4_HVState_18 "汇流排4上高压状态                                    ";
CM_ SG_ 2332487330 M2P_BUS5_HVState_18 "汇流排5上高压状态                                    ";
CM_ SG_ 2332487330 M2P_BUS6_HVState_18 "汇流排6上高压状态                                    ";
CM_ SG_ 2332487330 M2P_BUS7_HVState_18 "汇流排7上高压状态                                    ";
CM_ SG_ 2332487330 M2P_BUS8_HVState_18 "汇流排8上高压状态                                    ";
CM_ SG_ 2332487330 M2P_BUS9_HVState_18 "汇流排9上高压状态                                    ";
CM_ SG_ 2332487330 M2P_BUS10_HVState_18 "汇流排10上高压状态                                    ";
CM_ SG_ 2332487330 M2P_BUS11_HVState_18 "汇流排11上高压状态                                    ";
CM_ SG_ 2332487330 M2P_BUS12_HVState_18 "汇流排12上高压状态                                    ";
CM_ SG_ 2332487331 M2P_PermitMaxPower_Charge_19 "系统最大允许充电功率";
CM_ SG_ 2332487331 M2P_PermitMaxPower_DisCharge_19 "系统最大允许放电功率";
CM_ SG_ 2332487331 M2P_Power_19 "系统实时功率";
CM_ SG_ 2332487331 M2P_StepChrMode_19 "系统Step-Charge模式";
CM_ SG_ 2332487331 M2P_BUS1_HVState_19 "汇流排1上高压状态                                    ";
CM_ SG_ 2332487331 M2P_BUS2_HVState_19 "汇流排2上高压状态                                    ";
CM_ SG_ 2332487331 M2P_BUS3_HVState_19 "汇流排3上高压状态                                    ";
CM_ SG_ 2332487331 M2P_BUS4_HVState_19 "汇流排4上高压状态                                    ";
CM_ SG_ 2332487331 M2P_BUS5_HVState_19 "汇流排5上高压状态                                    ";
CM_ SG_ 2332487331 M2P_BUS6_HVState_19 "汇流排6上高压状态                                    ";
CM_ SG_ 2332487331 M2P_BUS7_HVState_19 "汇流排7上高压状态                                    ";
CM_ SG_ 2332487331 M2P_BUS8_HVState_19 "汇流排8上高压状态                                    ";
CM_ SG_ 2332487331 M2P_BUS9_HVState_19 "汇流排9上高压状态                                    ";
CM_ SG_ 2332487331 M2P_BUS10_HVState_19 "汇流排10上高压状态                                    ";
CM_ SG_ 2332487331 M2P_BUS11_HVState_19 "汇流排11上高压状态                                    ";
CM_ SG_ 2332487331 M2P_BUS12_HVState_19 "汇流排12上高压状态                                    ";
CM_ SG_ 2332487332 M2P_PermitMaxPower_Charge_20 "系统最大允许充电功率";
CM_ SG_ 2332487332 M2P_PermitMaxPower_DisCharge_20 "系统最大允许放电功率";
CM_ SG_ 2332487332 M2P_Power_20 "系统实时功率";
CM_ SG_ 2332487332 M2P_StepChrMode_20 "系统Step-Charge模式";
CM_ SG_ 2332487332 M2P_BUS1_HVState_20 "汇流排1上高压状态                                    ";
CM_ SG_ 2332487332 M2P_BUS2_HVState_20 "汇流排2上高压状态                                    ";
CM_ SG_ 2332487332 M2P_BUS3_HVState_20 "汇流排3上高压状态                                    ";
CM_ SG_ 2332487332 M2P_BUS4_HVState_20 "汇流排4上高压状态                                    ";
CM_ SG_ 2332487332 M2P_BUS5_HVState_20 "汇流排5上高压状态                                    ";
CM_ SG_ 2332487332 M2P_BUS6_HVState_20 "汇流排6上高压状态                                    ";
CM_ SG_ 2332487332 M2P_BUS7_HVState_20 "汇流排7上高压状态                                    ";
CM_ SG_ 2332487332 M2P_BUS8_HVState_20 "汇流排8上高压状态                                    ";
CM_ SG_ 2332487332 M2P_BUS9_HVState_20 "汇流排9上高压状态                                    ";
CM_ SG_ 2332487332 M2P_BUS10_HVState_20 "汇流排10上高压状态                                    ";
CM_ SG_ 2332487332 M2P_BUS11_HVState_20 "汇流排11上高压状态                                    ";
CM_ SG_ 2332487332 M2P_BUS12_HVState_20 "汇流排12上高压状态                                    ";
CM_ SG_ 2332487333 M2P_PermitMaxPower_Charge_21 "系统最大允许充电功率";
CM_ SG_ 2332487333 M2P_PermitMaxPower_DisCharge_21 "系统最大允许放电功率";
CM_ SG_ 2332487333 M2P_Power_21 "系统实时功率";
CM_ SG_ 2332487333 M2P_StepChrMode_21 "系统Step-Charge模式";
CM_ SG_ 2332487333 M2P_BUS1_HVState_21 "汇流排1上高压状态                                    ";
CM_ SG_ 2332487333 M2P_BUS2_HVState_21 "汇流排2上高压状态                                    ";
CM_ SG_ 2332487333 M2P_BUS3_HVState_21 "汇流排3上高压状态                                    ";
CM_ SG_ 2332487333 M2P_BUS4_HVState_21 "汇流排4上高压状态                                    ";
CM_ SG_ 2332487333 M2P_BUS5_HVState_21 "汇流排5上高压状态                                    ";
CM_ SG_ 2332487333 M2P_BUS6_HVState_21 "汇流排6上高压状态                                    ";
CM_ SG_ 2332487333 M2P_BUS7_HVState_21 "汇流排7上高压状态                                    ";
CM_ SG_ 2332487333 M2P_BUS8_HVState_21 "汇流排8上高压状态                                    ";
CM_ SG_ 2332487333 M2P_BUS9_HVState_21 "汇流排9上高压状态                                    ";
CM_ SG_ 2332487333 M2P_BUS10_HVState_21 "汇流排10上高压状态                                    ";
CM_ SG_ 2332487333 M2P_BUS11_HVState_21 "汇流排11上高压状态                                    ";
CM_ SG_ 2332487333 M2P_BUS12_HVState_21 "汇流排12上高压状态                                    ";
CM_ SG_ 2332487334 M2P_PermitMaxPower_Charge_22 "系统最大允许充电功率";
CM_ SG_ 2332487334 M2P_PermitMaxPower_DisCharge_22 "系统最大允许放电功率";
CM_ SG_ 2332487334 M2P_Power_22 "系统实时功率";
CM_ SG_ 2332487334 M2P_StepChrMode_22 "系统Step-Charge模式";
CM_ SG_ 2332487334 M2P_BUS1_HVState_22 "汇流排1上高压状态                                    ";
CM_ SG_ 2332487334 M2P_BUS2_HVState_22 "汇流排2上高压状态                                    ";
CM_ SG_ 2332487334 M2P_BUS3_HVState_22 "汇流排3上高压状态                                    ";
CM_ SG_ 2332487334 M2P_BUS4_HVState_22 "汇流排4上高压状态                                    ";
CM_ SG_ 2332487334 M2P_BUS5_HVState_22 "汇流排5上高压状态                                    ";
CM_ SG_ 2332487334 M2P_BUS6_HVState_22 "汇流排6上高压状态                                    ";
CM_ SG_ 2332487334 M2P_BUS7_HVState_22 "汇流排7上高压状态                                    ";
CM_ SG_ 2332487334 M2P_BUS8_HVState_22 "汇流排8上高压状态                                    ";
CM_ SG_ 2332487334 M2P_BUS9_HVState_22 "汇流排9上高压状态                                    ";
CM_ SG_ 2332487334 M2P_BUS10_HVState_22 "汇流排10上高压状态                                    ";
CM_ SG_ 2332487334 M2P_BUS11_HVState_22 "汇流排11上高压状态                                    ";
CM_ SG_ 2332487334 M2P_BUS12_HVState_22 "汇流排12上高压状态                                    ";
CM_ SG_ 2332487335 M2P_PermitMaxPower_Charge_23 "系统最大允许充电功率";
CM_ SG_ 2332487335 M2P_PermitMaxPower_DisCharge_23 "系统最大允许放电功率";
CM_ SG_ 2332487335 M2P_Power_23 "系统实时功率";
CM_ SG_ 2332487335 M2P_StepChrMode_23 "系统Step-Charge模式";
CM_ SG_ 2332487335 M2P_BUS1_HVState_23 "汇流排1上高压状态                                    ";
CM_ SG_ 2332487335 M2P_BUS2_HVState_23 "汇流排2上高压状态                                    ";
CM_ SG_ 2332487335 M2P_BUS3_HVState_23 "汇流排3上高压状态                                    ";
CM_ SG_ 2332487335 M2P_BUS4_HVState_23 "汇流排4上高压状态                                    ";
CM_ SG_ 2332487335 M2P_BUS5_HVState_23 "汇流排5上高压状态                                    ";
CM_ SG_ 2332487335 M2P_BUS6_HVState_23 "汇流排6上高压状态                                    ";
CM_ SG_ 2332487335 M2P_BUS7_HVState_23 "汇流排7上高压状态                                    ";
CM_ SG_ 2332487335 M2P_BUS8_HVState_23 "汇流排8上高压状态                                    ";
CM_ SG_ 2332487335 M2P_BUS9_HVState_23 "汇流排9上高压状态                                    ";
CM_ SG_ 2332487335 M2P_BUS10_HVState_23 "汇流排10上高压状态                                    ";
CM_ SG_ 2332487335 M2P_BUS11_HVState_23 "汇流排11上高压状态                                    ";
CM_ SG_ 2332487335 M2P_BUS12_HVState_23 "汇流排12上高压状态                                    ";
CM_ SG_ 2332487336 M2P_PermitMaxPower_Charge_24 "系统最大允许充电功率";
CM_ SG_ 2332487336 M2P_PermitMaxPower_DisCharge_24 "系统最大允许放电功率";
CM_ SG_ 2332487336 M2P_Power_24 "系统实时功率";
CM_ SG_ 2332487336 M2P_StepChrMode_24 "系统Step-Charge模式";
CM_ SG_ 2332487336 M2P_BUS1_HVState_24 "汇流排1上高压状态                                    ";
CM_ SG_ 2332487336 M2P_BUS2_HVState_24 "汇流排2上高压状态                                    ";
CM_ SG_ 2332487336 M2P_BUS3_HVState_24 "汇流排3上高压状态                                    ";
CM_ SG_ 2332487336 M2P_BUS4_HVState_24 "汇流排4上高压状态                                    ";
CM_ SG_ 2332487336 M2P_BUS5_HVState_24 "汇流排5上高压状态                                    ";
CM_ SG_ 2332487336 M2P_BUS6_HVState_24 "汇流排6上高压状态                                    ";
CM_ SG_ 2332487336 M2P_BUS7_HVState_24 "汇流排7上高压状态                                    ";
CM_ SG_ 2332487336 M2P_BUS8_HVState_24 "汇流排8上高压状态                                    ";
CM_ SG_ 2332487336 M2P_BUS9_HVState_24 "汇流排9上高压状态                                    ";
CM_ SG_ 2332487336 M2P_BUS10_HVState_24 "汇流排10上高压状态                                    ";
CM_ SG_ 2332487336 M2P_BUS11_HVState_24 "汇流排11上高压状态                                    ";
CM_ SG_ 2332487336 M2P_BUS12_HVState_24 "汇流排12上高压状态                                    ";
CM_ SG_ 2332487337 M2P_PermitMaxPower_Charge_25 "系统最大允许充电功率";
CM_ SG_ 2332487337 M2P_PermitMaxPower_DisCharge_25 "系统最大允许放电功率";
CM_ SG_ 2332487337 M2P_Power_25 "系统实时功率";
CM_ SG_ 2332487337 M2P_StepChrMode_25 "系统Step-Charge模式";
CM_ SG_ 2332487337 M2P_BUS1_HVState_25 "汇流排1上高压状态                                    ";
CM_ SG_ 2332487337 M2P_BUS2_HVState_25 "汇流排2上高压状态                                    ";
CM_ SG_ 2332487337 M2P_BUS3_HVState_25 "汇流排3上高压状态                                    ";
CM_ SG_ 2332487337 M2P_BUS4_HVState_25 "汇流排4上高压状态                                    ";
CM_ SG_ 2332487337 M2P_BUS5_HVState_25 "汇流排5上高压状态                                    ";
CM_ SG_ 2332487337 M2P_BUS6_HVState_25 "汇流排6上高压状态                                    ";
CM_ SG_ 2332487337 M2P_BUS7_HVState_25 "汇流排7上高压状态                                    ";
CM_ SG_ 2332487337 M2P_BUS8_HVState_25 "汇流排8上高压状态                                    ";
CM_ SG_ 2332487337 M2P_BUS9_HVState_25 "汇流排9上高压状态                                    ";
CM_ SG_ 2332487337 M2P_BUS10_HVState_25 "汇流排10上高压状态                                    ";
CM_ SG_ 2332487337 M2P_BUS11_HVState_25 "汇流排11上高压状态                                    ";
CM_ SG_ 2332487337 M2P_BUS12_HVState_25 "汇流排12上高压状态                                    ";
CM_ SG_ 2332487338 M2P_PermitMaxPower_Charge_26 "系统最大允许充电功率";
CM_ SG_ 2332487338 M2P_PermitMaxPower_DisCharge_26 "系统最大允许放电功率";
CM_ SG_ 2332487338 M2P_Power_26 "系统实时功率";
CM_ SG_ 2332487338 M2P_StepChrMode_26 "系统Step-Charge模式";
CM_ SG_ 2332487338 M2P_BUS1_HVState_26 "汇流排1上高压状态                                    ";
CM_ SG_ 2332487338 M2P_BUS2_HVState_26 "汇流排2上高压状态                                    ";
CM_ SG_ 2332487338 M2P_BUS3_HVState_26 "汇流排3上高压状态                                    ";
CM_ SG_ 2332487338 M2P_BUS4_HVState_26 "汇流排4上高压状态                                    ";
CM_ SG_ 2332487338 M2P_BUS5_HVState_26 "汇流排5上高压状态                                    ";
CM_ SG_ 2332487338 M2P_BUS6_HVState_26 "汇流排6上高压状态                                    ";
CM_ SG_ 2332487338 M2P_BUS7_HVState_26 "汇流排7上高压状态                                    ";
CM_ SG_ 2332487338 M2P_BUS8_HVState_26 "汇流排8上高压状态                                    ";
CM_ SG_ 2332487338 M2P_BUS9_HVState_26 "汇流排9上高压状态                                    ";
CM_ SG_ 2332487338 M2P_BUS10_HVState_26 "汇流排10上高压状态                                    ";
CM_ SG_ 2332487338 M2P_BUS11_HVState_26 "汇流排11上高压状态                                    ";
CM_ SG_ 2332487338 M2P_BUS12_HVState_26 "汇流排12上高压状态                                    ";
CM_ SG_ 2332487339 M2P_PermitMaxPower_Charge_27 "系统最大允许充电功率";
CM_ SG_ 2332487339 M2P_PermitMaxPower_DisCharge_27 "系统最大允许放电功率";
CM_ SG_ 2332487339 M2P_Power_27 "系统实时功率";
CM_ SG_ 2332487339 M2P_StepChrMode_27 "系统Step-Charge模式";
CM_ SG_ 2332487339 M2P_BUS1_HVState_27 "汇流排1上高压状态                                    ";
CM_ SG_ 2332487339 M2P_BUS2_HVState_27 "汇流排2上高压状态                                    ";
CM_ SG_ 2332487339 M2P_BUS3_HVState_27 "汇流排3上高压状态                                    ";
CM_ SG_ 2332487339 M2P_BUS4_HVState_27 "汇流排4上高压状态                                    ";
CM_ SG_ 2332487339 M2P_BUS5_HVState_27 "汇流排5上高压状态                                    ";
CM_ SG_ 2332487339 M2P_BUS6_HVState_27 "汇流排6上高压状态                                    ";
CM_ SG_ 2332487339 M2P_BUS7_HVState_27 "汇流排7上高压状态                                    ";
CM_ SG_ 2332487339 M2P_BUS8_HVState_27 "汇流排8上高压状态                                    ";
CM_ SG_ 2332487339 M2P_BUS9_HVState_27 "汇流排9上高压状态                                    ";
CM_ SG_ 2332487339 M2P_BUS10_HVState_27 "汇流排10上高压状态                                    ";
CM_ SG_ 2332487339 M2P_BUS11_HVState_27 "汇流排11上高压状态                                    ";
CM_ SG_ 2332487339 M2P_BUS12_HVState_27 "汇流排12上高压状态                                    ";
CM_ SG_ 2332487340 M2P_PermitMaxPower_Charge_28 "系统最大允许充电功率";
CM_ SG_ 2332487340 M2P_PermitMaxPower_DisCharge_28 "系统最大允许放电功率";
CM_ SG_ 2332487340 M2P_Power_28 "系统实时功率";
CM_ SG_ 2332487340 M2P_StepChrMode_28 "系统Step-Charge模式";
CM_ SG_ 2332487340 M2P_BUS1_HVState_28 "汇流排1上高压状态                                    ";
CM_ SG_ 2332487340 M2P_BUS2_HVState_28 "汇流排2上高压状态                                    ";
CM_ SG_ 2332487340 M2P_BUS3_HVState_28 "汇流排3上高压状态                                    ";
CM_ SG_ 2332487340 M2P_BUS4_HVState_28 "汇流排4上高压状态                                    ";
CM_ SG_ 2332487340 M2P_BUS5_HVState_28 "汇流排5上高压状态                                    ";
CM_ SG_ 2332487340 M2P_BUS6_HVState_28 "汇流排6上高压状态                                    ";
CM_ SG_ 2332487340 M2P_BUS7_HVState_28 "汇流排7上高压状态                                    ";
CM_ SG_ 2332487340 M2P_BUS8_HVState_28 "汇流排8上高压状态                                    ";
CM_ SG_ 2332487340 M2P_BUS9_HVState_28 "汇流排9上高压状态                                    ";
CM_ SG_ 2332487340 M2P_BUS10_HVState_28 "汇流排10上高压状态                                    ";
CM_ SG_ 2332487340 M2P_BUS11_HVState_28 "汇流排11上高压状态                                    ";
CM_ SG_ 2332487340 M2P_BUS12_HVState_28 "汇流排12上高压状态                                    ";
CM_ SG_ 2332487341 M2P_PermitMaxPower_Charge_29 "系统最大允许充电功率";
CM_ SG_ 2332487341 M2P_PermitMaxPower_DisCharge_29 "系统最大允许放电功率";
CM_ SG_ 2332487341 M2P_Power_29 "系统实时功率";
CM_ SG_ 2332487341 M2P_StepChrMode_29 "系统Step-Charge模式";
CM_ SG_ 2332487341 M2P_BUS1_HVState_29 "汇流排1上高压状态                                    ";
CM_ SG_ 2332487341 M2P_BUS2_HVState_29 "汇流排2上高压状态                                    ";
CM_ SG_ 2332487341 M2P_BUS3_HVState_29 "汇流排3上高压状态                                    ";
CM_ SG_ 2332487341 M2P_BUS4_HVState_29 "汇流排4上高压状态                                    ";
CM_ SG_ 2332487341 M2P_BUS5_HVState_29 "汇流排5上高压状态                                    ";
CM_ SG_ 2332487341 M2P_BUS6_HVState_29 "汇流排6上高压状态                                    ";
CM_ SG_ 2332487341 M2P_BUS7_HVState_29 "汇流排7上高压状态                                    ";
CM_ SG_ 2332487341 M2P_BUS8_HVState_29 "汇流排8上高压状态                                    ";
CM_ SG_ 2332487341 M2P_BUS9_HVState_29 "汇流排9上高压状态                                    ";
CM_ SG_ 2332487341 M2P_BUS10_HVState_29 "汇流排10上高压状态                                    ";
CM_ SG_ 2332487341 M2P_BUS11_HVState_29 "汇流排11上高压状态                                    ";
CM_ SG_ 2332487341 M2P_BUS12_HVState_29 "汇流排12上高压状态                                    ";
CM_ SG_ 2332487342 M2P_PermitMaxPower_Charge_30 "系统最大允许充电功率";
CM_ SG_ 2332487342 M2P_PermitMaxPower_DisCharge_30 "系统最大允许放电功率";
CM_ SG_ 2332487342 M2P_Power_30 "系统实时功率";
CM_ SG_ 2332487342 M2P_StepChrMode_30 "系统Step-Charge模式";
CM_ SG_ 2332487342 M2P_BUS1_HVState_30 "汇流排1上高压状态                                    ";
CM_ SG_ 2332487342 M2P_BUS2_HVState_30 "汇流排2上高压状态                                    ";
CM_ SG_ 2332487342 M2P_BUS3_HVState_30 "汇流排3上高压状态                                    ";
CM_ SG_ 2332487342 M2P_BUS4_HVState_30 "汇流排4上高压状态                                    ";
CM_ SG_ 2332487342 M2P_BUS5_HVState_30 "汇流排5上高压状态                                    ";
CM_ SG_ 2332487342 M2P_BUS6_HVState_30 "汇流排6上高压状态                                    ";
CM_ SG_ 2332487342 M2P_BUS7_HVState_30 "汇流排7上高压状态                                    ";
CM_ SG_ 2332487342 M2P_BUS8_HVState_30 "汇流排8上高压状态                                    ";
CM_ SG_ 2332487342 M2P_BUS9_HVState_30 "汇流排9上高压状态                                    ";
CM_ SG_ 2332487342 M2P_BUS10_HVState_30 "汇流排10上高压状态                                    ";
CM_ SG_ 2332487342 M2P_BUS11_HVState_30 "汇流排11上高压状态                                    ";
CM_ SG_ 2332487342 M2P_BUS12_HVState_30 "汇流排12上高压状态                                    ";
CM_ SG_ 2332487343 M2P_PermitMaxPower_Charge_31 "系统最大允许充电功率";
CM_ SG_ 2332487343 M2P_PermitMaxPower_DisCharge_31 "系统最大允许放电功率";
CM_ SG_ 2332487343 M2P_Power_31 "系统实时功率";
CM_ SG_ 2332487343 M2P_StepChrMode_31 "系统Step-Charge模式";
CM_ SG_ 2332487343 M2P_BUS1_HVState_31 "汇流排1上高压状态                                    ";
CM_ SG_ 2332487343 M2P_BUS2_HVState_31 "汇流排2上高压状态                                    ";
CM_ SG_ 2332487343 M2P_BUS3_HVState_31 "汇流排3上高压状态                                    ";
CM_ SG_ 2332487343 M2P_BUS4_HVState_31 "汇流排4上高压状态                                    ";
CM_ SG_ 2332487343 M2P_BUS5_HVState_31 "汇流排5上高压状态                                    ";
CM_ SG_ 2332487343 M2P_BUS6_HVState_31 "汇流排6上高压状态                                    ";
CM_ SG_ 2332487343 M2P_BUS7_HVState_31 "汇流排7上高压状态                                    ";
CM_ SG_ 2332487343 M2P_BUS8_HVState_31 "汇流排8上高压状态                                    ";
CM_ SG_ 2332487343 M2P_BUS9_HVState_31 "汇流排9上高压状态                                    ";
CM_ SG_ 2332487343 M2P_BUS10_HVState_31 "汇流排10上高压状态                                    ";
CM_ SG_ 2332487343 M2P_BUS11_HVState_31 "汇流排11上高压状态                                    ";
CM_ SG_ 2332487343 M2P_BUS12_HVState_31 "汇流排12上高压状态                                    ";
CM_ SG_ 2332552849 M2P_SysremainEngy_Charge_01 "系统充电剩余能量";
CM_ SG_ 2332552849 M2P_SysremainEngy_DisCharge_01 "系统放电剩余能量";
CM_ SG_ 2332552849 M2P_SOE_Charge_01 "系统可充电SOE";
CM_ SG_ 2332552849 M2P_SOE_Discharge_01 "系统可放电SOE";
CM_ SG_ 2332552850 M2P_SysremainEngy_Charge_02 "系统充电剩余能量";
CM_ SG_ 2332552850 M2P_SysremainEngy_DisCharge_02 "系统放电剩余能量";
CM_ SG_ 2332552850 M2P_SOE_Charge_02 "系统可充电SOE";
CM_ SG_ 2332552850 M2P_SOE_Discharge_02 "系统可放电SOE";
CM_ SG_ 2332552851 M2P_SysremainEngy_Charge_03 "系统充电剩余能量";
CM_ SG_ 2332552851 M2P_SysremainEngy_DisCharge_03 "系统放电剩余能量";
CM_ SG_ 2332552851 M2P_SOE_Charge_03 "系统可充电SOE";
CM_ SG_ 2332552851 M2P_SOE_Discharge_03 "系统可放电SOE";
CM_ SG_ 2332552852 M2P_SysremainEngy_Charge_04 "系统充电剩余能量";
CM_ SG_ 2332552852 M2P_SysremainEngy_DisCharge_04 "系统放电剩余能量";
CM_ SG_ 2332552852 M2P_SOE_Charge_04 "系统可充电SOE";
CM_ SG_ 2332552852 M2P_SOE_Discharge_04 "系统可放电SOE";
CM_ SG_ 2332552853 M2P_SysremainEngy_Charge_05 "系统充电剩余能量";
CM_ SG_ 2332552853 M2P_SysremainEngy_DisCharge_05 "系统放电剩余能量";
CM_ SG_ 2332552853 M2P_SOE_Charge_05 "系统可充电SOE";
CM_ SG_ 2332552853 M2P_SOE_Discharge_05 "系统可放电SOE";
CM_ SG_ 2332552854 M2P_SysremainEngy_Charge_06 "系统充电剩余能量";
CM_ SG_ 2332552854 M2P_SysremainEngy_DisCharge_06 "系统放电剩余能量";
CM_ SG_ 2332552854 M2P_SOE_Charge_06 "系统可充电SOE";
CM_ SG_ 2332552854 M2P_SOE_Discharge_06 "系统可放电SOE";
CM_ SG_ 2332552855 M2P_SysremainEngy_Charge_07 "系统充电剩余能量";
CM_ SG_ 2332552855 M2P_SysremainEngy_DisCharge_07 "系统放电剩余能量";
CM_ SG_ 2332552855 M2P_SOE_Charge_07 "系统可充电SOE";
CM_ SG_ 2332552855 M2P_SOE_Discharge_07 "系统可放电SOE";
CM_ SG_ 2332552856 M2P_SysremainEngy_Charge_08 "系统充电剩余能量";
CM_ SG_ 2332552856 M2P_SysremainEngy_DisCharge_08 "系统放电剩余能量";
CM_ SG_ 2332552856 M2P_SOE_Charge_08 "系统可充电SOE";
CM_ SG_ 2332552856 M2P_SOE_Discharge_08 "系统可放电SOE";
CM_ SG_ 2332552857 M2P_SysremainEngy_Charge_09 "系统充电剩余能量";
CM_ SG_ 2332552857 M2P_SysremainEngy_DisCharge_09 "系统放电剩余能量";
CM_ SG_ 2332552857 M2P_SOE_Charge_09 "系统可充电SOE";
CM_ SG_ 2332552857 M2P_SOE_Discharge_09 "系统可放电SOE";
CM_ SG_ 2332552858 M2P_SysremainEngy_Charge_10 "系统充电剩余能量";
CM_ SG_ 2332552858 M2P_SysremainEngy_DisCharge_10 "系统放电剩余能量";
CM_ SG_ 2332552858 M2P_SOE_Charge_10 "系统可充电SOE";
CM_ SG_ 2332552858 M2P_SOE_Discharge_10 "系统可放电SOE";
CM_ SG_ 2332552859 M2P_SysremainEngy_Charge_11 "系统充电剩余能量";
CM_ SG_ 2332552859 M2P_SysremainEngy_DisCharge_11 "系统放电剩余能量";
CM_ SG_ 2332552859 M2P_SOE_Charge_11 "系统可充电SOE";
CM_ SG_ 2332552859 M2P_SOE_Discharge_11 "系统可放电SOE";
CM_ SG_ 2332552860 M2P_SysremainEngy_Charge_12 "系统充电剩余能量";
CM_ SG_ 2332552860 M2P_SysremainEngy_DisCharge_12 "系统放电剩余能量";
CM_ SG_ 2332552860 M2P_SOE_Charge_12 "系统可充电SOE";
CM_ SG_ 2332552860 M2P_SOE_Discharge_12 "系统可放电SOE";
CM_ SG_ 2332552861 M2P_SysremainEngy_Charge_13 "系统充电剩余能量";
CM_ SG_ 2332552861 M2P_SysremainEngy_DisCharge_13 "系统放电剩余能量";
CM_ SG_ 2332552861 M2P_SOE_Charge_13 "系统可充电SOE";
CM_ SG_ 2332552861 M2P_SOE_Discharge_13 "系统可放电SOE";
CM_ SG_ 2332552862 M2P_SysremainEngy_Charge_14 "系统充电剩余能量";
CM_ SG_ 2332552862 M2P_SysremainEngy_DisCharge_14 "系统放电剩余能量";
CM_ SG_ 2332552862 M2P_SOE_Charge_14 "系统可充电SOE";
CM_ SG_ 2332552862 M2P_SOE_Discharge_14 "系统可放电SOE";
CM_ SG_ 2332552863 M2P_SysremainEngy_Charge_15 "系统充电剩余能量";
CM_ SG_ 2332552863 M2P_SysremainEngy_DisCharge_15 "系统放电剩余能量";
CM_ SG_ 2332552863 M2P_SOE_Charge_15 "系统可充电SOE";
CM_ SG_ 2332552863 M2P_SOE_Discharge_15 "系统可放电SOE";
CM_ SG_ 2332552864 M2P_SysremainEngy_Charge_16 "系统充电剩余能量";
CM_ SG_ 2332552864 M2P_SysremainEngy_DisCharge_16 "系统放电剩余能量";
CM_ SG_ 2332552864 M2P_SOE_Charge_16 "系统可充电SOE";
CM_ SG_ 2332552864 M2P_SOE_Discharge_16 "系统可放电SOE";
CM_ SG_ 2332552865 M2P_SysremainEngy_Charge_17 "系统充电剩余能量";
CM_ SG_ 2332552865 M2P_SysremainEngy_DisCharge_17 "系统放电剩余能量";
CM_ SG_ 2332552865 M2P_SOE_Charge_17 "系统可充电SOE";
CM_ SG_ 2332552865 M2P_SOE_Discharge_17 "系统可放电SOE";
CM_ SG_ 2332552866 M2P_SysremainEngy_Charge_18 "系统充电剩余能量";
CM_ SG_ 2332552866 M2P_SysremainEngy_DisCharge_18 "系统放电剩余能量";
CM_ SG_ 2332552866 M2P_SOE_Charge_18 "系统可充电SOE";
CM_ SG_ 2332552866 M2P_SOE_Discharge_18 "系统可放电SOE";
CM_ SG_ 2332552867 M2P_SysremainEngy_Charge_19 "系统充电剩余能量";
CM_ SG_ 2332552867 M2P_SysremainEngy_DisCharge_19 "系统放电剩余能量";
CM_ SG_ 2332552867 M2P_SOE_Charge_19 "系统可充电SOE";
CM_ SG_ 2332552867 M2P_SOE_Discharge_19 "系统可放电SOE";
CM_ SG_ 2332552868 M2P_SysremainEngy_Charge_20 "系统充电剩余能量";
CM_ SG_ 2332552868 M2P_SysremainEngy_DisCharge_20 "系统放电剩余能量";
CM_ SG_ 2332552868 M2P_SOE_Charge_20 "系统可充电SOE";
CM_ SG_ 2332552868 M2P_SOE_Discharge_20 "系统可放电SOE";
CM_ SG_ 2332552869 M2P_SysremainEngy_Charge_21 "系统充电剩余能量";
CM_ SG_ 2332552869 M2P_SysremainEngy_DisCharge_21 "系统放电剩余能量";
CM_ SG_ 2332552869 M2P_SOE_Charge_21 "系统可充电SOE";
CM_ SG_ 2332552869 M2P_SOE_Discharge_21 "系统可放电SOE";
CM_ SG_ 2332552870 M2P_SysremainEngy_Charge_22 "系统充电剩余能量";
CM_ SG_ 2332552870 M2P_SysremainEngy_DisCharge_22 "系统放电剩余能量";
CM_ SG_ 2332552870 M2P_SOE_Charge_22 "系统可充电SOE";
CM_ SG_ 2332552870 M2P_SOE_Discharge_22 "系统可放电SOE";
CM_ SG_ 2332552871 M2P_SysremainEngy_Charge_23 "系统充电剩余能量";
CM_ SG_ 2332552871 M2P_SysremainEngy_DisCharge_23 "系统放电剩余能量";
CM_ SG_ 2332552871 M2P_SOE_Charge_23 "系统可充电SOE";
CM_ SG_ 2332552871 M2P_SOE_Discharge_23 "系统可放电SOE";
CM_ SG_ 2332552872 M2P_SysremainEngy_Charge_24 "系统充电剩余能量";
CM_ SG_ 2332552872 M2P_SysremainEngy_DisCharge_24 "系统放电剩余能量";
CM_ SG_ 2332552872 M2P_SOE_Charge_24 "系统可充电SOE";
CM_ SG_ 2332552872 M2P_SOE_Discharge_24 "系统可放电SOE";
CM_ SG_ 2332552873 M2P_SysremainEngy_Charge_25 "系统充电剩余能量";
CM_ SG_ 2332552873 M2P_SysremainEngy_DisCharge_25 "系统放电剩余能量";
CM_ SG_ 2332552873 M2P_SOE_Charge_25 "系统可充电SOE";
CM_ SG_ 2332552873 M2P_SOE_Discharge_25 "系统可放电SOE";
CM_ SG_ 2332552874 M2P_SysremainEngy_Charge_26 "系统充电剩余能量";
CM_ SG_ 2332552874 M2P_SysremainEngy_DisCharge_26 "系统放电剩余能量";
CM_ SG_ 2332552874 M2P_SOE_Charge_26 "系统可充电SOE";
CM_ SG_ 2332552874 M2P_SOE_Discharge_26 "系统可放电SOE";
VAL_ 2332290731 M2P_PermitMaxCharge_I_27 65535 "Invalid" ;
VAL_ 2332290731 M2P_PermitMaxDisCharge_I_27 65535 "Invalid" ;
VAL_ 2332290731 M2P_Evn_T1_27 204 "干接点使用/未作温度采样使用" 205 "无效" ;
VAL_ 2332290731 M2P_Evn_T2_27 204 "干接点使用/未作温度采样使用" 205 "无效" ;
VAL_ 2332290731 M2P_Evn_T3_27 204 "干接点使用/未作温度采样使用" 205 "无效" ;
VAL_ 2332290731 M2P_Evn_Humidity_27 255 "Invalid" ;
VAL_ 2332290732 M2P_PermitMaxCharge_I_28 65535 "Invalid" ;
VAL_ 2332290732 M2P_PermitMaxDisCharge_I_28 65535 "Invalid" ;
VAL_ 2332290732 M2P_Evn_T1_28 204 "干接点使用/未作温度采样使用" 205 "无效" ;
VAL_ 2332290732 M2P_Evn_T2_28 204 "干接点使用/未作温度采样使用" 205 "无效" ;
VAL_ 2332290732 M2P_Evn_T3_28 204 "干接点使用/未作温度采样使用" 205 "无效" ;
VAL_ 2332290732 M2P_Evn_Humidity_28 255 "Invalid" ;
VAL_ 2332290733 M2P_PermitMaxCharge_I_29 65535 "Invalid" ;
VAL_ 2332290733 M2P_PermitMaxDisCharge_I_29 65535 "Invalid" ;
VAL_ 2332290733 M2P_Evn_T1_29 204 "干接点使用/未作温度采样使用" 205 "无效" ;
VAL_ 2332290733 M2P_Evn_T2_29 204 "干接点使用/未作温度采样使用" 205 "无效" ;
VAL_ 2332290733 M2P_Evn_T3_29 204 "干接点使用/未作温度采样使用" 205 "无效" ;
VAL_ 2332290733 M2P_Evn_Humidity_29 255 "Invalid" ;
VAL_ 2332290734 M2P_PermitMaxCharge_I_30 65535 "Invalid" ;
VAL_ 2332290734 M2P_PermitMaxDisCharge_I_30 65535 "Invalid" ;
VAL_ 2332290734 M2P_Evn_T1_30 204 "干接点使用/未作温度采样使用" 205 "无效" ;
VAL_ 2332290734 M2P_Evn_T2_30 204 "干接点使用/未作温度采样使用" 205 "无效" ;
VAL_ 2332290734 M2P_Evn_T3_30 204 "干接点使用/未作温度采样使用" 205 "无效" ;
VAL_ 2332290734 M2P_Evn_Humidity_30 255 "Invalid" ;
VAL_ 2332290735 M2P_PermitMaxCharge_I_31 65535 "Invalid" ;
VAL_ 2332290735 M2P_PermitMaxDisCharge_I_31 65535 "Invalid" ;
VAL_ 2332290735 M2P_Evn_T1_31 204 "干接点使用/未作温度采样使用" 205 "无效" ;
VAL_ 2332290735 M2P_Evn_T2_31 204 "干接点使用/未作温度采样使用" 205 "无效" ;
VAL_ 2332290735 M2P_Evn_T3_31 204 "干接点使用/未作温度采样使用" 205 "无效" ;
VAL_ 2332290735 M2P_Evn_Humidity_31 255 "Invalid" ;
VAL_ 2332356241 M2P_Evn_T4_01 204 "干接点使用/未作温度采样使用" 205 "无效" ;
VAL_ 2332356241 M2P_Bat_CorrectState_Require_01 0 "无请求" 1 "请求维护" ;
VAL_ 2332356242 M2P_Evn_T4_02 204 "干接点使用/未作温度采样使用" 205 "无效" ;
VAL_ 2332356242 M2P_Bat_CorrectState_Require_02 0 "无请求" 1 "请求维护" ;
VAL_ 2332356243 M2P_Evn_T4_03 204 "干接点使用/未作温度采样使用" 205 "无效" ;
VAL_ 2332356243 M2P_Bat_CorrectState_Require_03 0 "无请求" 1 "请求维护" ;
VAL_ 2332356244 M2P_Evn_T4_04 204 "干接点使用/未作温度采样使用" 205 "无效" ;
VAL_ 2332356244 M2P_Bat_CorrectState_Require_04 0 "无请求" 1 "请求维护" ;
VAL_ 2332356245 M2P_Evn_T4_05 204 "干接点使用/未作温度采样使用" 205 "无效" ;
VAL_ 2332356245 M2P_Bat_CorrectState_Require_05 0 "无请求" 1 "请求维护" ;
VAL_ 2332356246 M2P_Evn_T4_06 204 "干接点使用/未作温度采样使用" 205 "无效" ;
VAL_ 2332356246 M2P_Bat_CorrectState_Require_06 0 "无请求" 1 "请求维护" ;
VAL_ 2332356247 M2P_Evn_T4_07 204 "干接点使用/未作温度采样使用" 205 "无效" ;
VAL_ 2332356247 M2P_Bat_CorrectState_Require_07 0 "无请求" 1 "请求维护" ;
VAL_ 2332356248 M2P_Evn_T4_08 204 "干接点使用/未作温度采样使用" 205 "无效" ;
VAL_ 2332356248 M2P_Bat_CorrectState_Require_08 0 "无请求" 1 "请求维护" ;
VAL_ 2332356249 M2P_Evn_T4_09 204 "干接点使用/未作温度采样使用" 205 "无效" ;
VAL_ 2332356249 M2P_Bat_CorrectState_Require_09 0 "无请求" 1 "请求维护" ;
VAL_ 2332356250 M2P_Evn_T4_10 204 "干接点使用/未作温度采样使用" 205 "无效" ;
VAL_ 2332356250 M2P_Bat_CorrectState_Require_10 0 "无请求" 1 "请求维护" ;
VAL_ 2332356251 M2P_Evn_T4_11 204 "干接点使用/未作温度采样使用" 205 "无效" ;
VAL_ 2332356251 M2P_Bat_CorrectState_Require_11 0 "无请求" 1 "请求维护" ;
VAL_ 2332356252 M2P_Evn_T4_12 204 "干接点使用/未作温度采样使用" 205 "无效" ;
VAL_ 2332356252 M2P_Bat_CorrectState_Require_12 0 "无请求" 1 "请求维护" ;
VAL_ 2332356253 M2P_Evn_T4_13 204 "干接点使用/未作温度采样使用" 205 "无效" ;
VAL_ 2332356253 M2P_Bat_CorrectState_Require_13 0 "无请求" 1 "请求维护" ;
VAL_ 2332356254 M2P_Evn_T4_14 204 "干接点使用/未作温度采样使用" 205 "无效" ;
VAL_ 2332356254 M2P_Bat_CorrectState_Require_14 0 "无请求" 1 "请求维护" ;
VAL_ 2332356255 M2P_Evn_T4_15 204 "干接点使用/未作温度采样使用" 205 "无效" ;
VAL_ 2332356255 M2P_Bat_CorrectState_Require_15 0 "无请求" 1 "请求维护" ;
VAL_ 2332356256 M2P_Evn_T4_16 204 "干接点使用/未作温度采样使用" 205 "无效" ;
VAL_ 2332356256 M2P_Bat_CorrectState_Require_16 0 "无请求" 1 "请求维护" ;
VAL_ 2332356257 M2P_Evn_T4_17 204 "干接点使用/未作温度采样使用" 205 "无效" ;
VAL_ 2332356257 M2P_Bat_CorrectState_Require_17 0 "无请求" 1 "请求维护" ;
VAL_ 2332356258 M2P_Evn_T4_18 204 "干接点使用/未作温度采样使用" 205 "无效" ;
VAL_ 2332356258 M2P_Bat_CorrectState_Require_18 0 "无请求" 1 "请求维护" ;
VAL_ 2332356259 M2P_Evn_T4_19 204 "干接点使用/未作温度采样使用" 205 "无效" ;
VAL_ 2332356259 M2P_Bat_CorrectState_Require_19 0 "无请求" 1 "请求维护" ;
VAL_ 2332356260 M2P_Evn_T4_20 204 "干接点使用/未作温度采样使用" 205 "无效" ;
VAL_ 2332356260 M2P_Bat_CorrectState_Require_20 0 "无请求" 1 "请求维护" ;
VAL_ 2332356261 M2P_Evn_T4_21 204 "干接点使用/未作温度采样使用" 205 "无效" ;
VAL_ 2332356261 M2P_Bat_CorrectState_Require_21 0 "无请求" 1 "请求维护" ;
VAL_ 2332356262 M2P_Evn_T4_22 204 "干接点使用/未作温度采样使用" 205 "无效" ;
VAL_ 2332356262 M2P_Bat_CorrectState_Require_22 0 "无请求" 1 "请求维护" ;
VAL_ 2332356263 M2P_Evn_T4_23 204 "干接点使用/未作温度采样使用" 205 "无效" ;
VAL_ 2332356263 M2P_Bat_CorrectState_Require_23 0 "无请求" 1 "请求维护" ;
VAL_ 2332356264 M2P_Evn_T4_24 204 "干接点使用/未作温度采样使用" 205 "无效" ;
VAL_ 2332356264 M2P_Bat_CorrectState_Require_24 0 "无请求" 1 "请求维护" ;
VAL_ 2332356265 M2P_Evn_T4_25 204 "干接点使用/未作温度采样使用" 205 "无效" ;
VAL_ 2332356265 M2P_Bat_CorrectState_Require_25 0 "无请求" 1 "请求维护" ;
VAL_ 2332356266 M2P_Evn_T4_26 204 "干接点使用/未作温度采样使用" 205 "无效" ;
VAL_ 2332356266 M2P_Bat_CorrectState_Require_26 0 "无请求" 1 "请求维护" ;
VAL_ 2332356267 M2P_Evn_T4_27 204 "干接点使用/未作温度采样使用" 205 "无效" ;
VAL_ 2332356267 M2P_Bat_CorrectState_Require_27 0 "无请求" 1 "请求维护" ;
VAL_ 2332356268 M2P_Evn_T4_28 204 "干接点使用/未作温度采样使用" 205 "无效" ;
VAL_ 2332356268 M2P_Bat_CorrectState_Require_28 0 "无请求" 1 "请求维护" ;
VAL_ 2332356269 M2P_Evn_T4_29 204 "干接点使用/未作温度采样使用" 205 "无效" ;
VAL_ 2332356269 M2P_Bat_CorrectState_Require_29 0 "无请求" 1 "请求维护" ;
VAL_ 2332356270 M2P_Evn_T4_30 204 "干接点使用/未作温度采样使用" 205 "无效" ;
VAL_ 2332356270 M2P_Bat_CorrectState_Require_30 0 "无请求" 1 "请求维护" ;
VAL_ 2332356271 M2P_Evn_T4_31 204 "干接点使用/未作温度采样使用" 205 "无效" ;
VAL_ 2332356271 M2P_Bat_CorrectState_Require_31 0 "无请求" 1 "请求维护" ;
VAL_ 2332421777 M2P_TMSCalibration_01 1 "仅管理TMS1（第1个电柜开始）" 3 "仅管理TMS2（第1个电柜开始）" ;
VAL_ 2332421777 M2P_IsoDetfunctionStatus_01 0 "无效" 1 "绝缘检测功能关闭" 2 "绝缘检测功能开启" ;
VAL_ 2332421777 M2P_TMS_Address_infor_01 0 "invalid" 1 "TMS1" 2 "TMS2" ;
VAL_ 2332421778 M2P_TMSCalibration_02 1 "仅管理TMS1（第1个电柜开始）" 3 "仅管理TMS2（第1个电柜开始）" ;
VAL_ 2332421778 M2P_IsoDetfunctionStatus_02 0 "无效" 1 "绝缘检测功能关闭" 2 "绝缘检测功能开启" ;
VAL_ 2332421778 M2P_TMS_Address_infor_02 0 "invalid" 1 "TMS1" 2 "TMS2" ;
VAL_ 2332421779 M2P_TMSCalibration_03 1 "仅管理TMS1（第1个电柜开始）" 3 "仅管理TMS2（第1个电柜开始）" ;
VAL_ 2332421779 M2P_IsoDetfunctionStatus_03 0 "无效" 1 "绝缘检测功能关闭" 2 "绝缘检测功能开启" ;
VAL_ 2332421779 M2P_TMS_Address_infor_03 0 "invalid" 1 "TMS1" 2 "TMS2" ;
VAL_ 2332421780 M2P_TMSCalibration_04 1 "仅管理TMS1（第1个电柜开始）" 3 "仅管理TMS2（第1个电柜开始）" ;
VAL_ 2332421780 M2P_IsoDetfunctionStatus_04 0 "无效" 1 "绝缘检测功能关闭" 2 "绝缘检测功能开启" ;
VAL_ 2332421780 M2P_TMS_Address_infor_04 0 "invalid" 1 "TMS1" 2 "TMS2" ;
VAL_ 2332421781 M2P_TMSCalibration_05 1 "仅管理TMS1（第1个电柜开始）" 3 "仅管理TMS2（第1个电柜开始）" ;
VAL_ 2332421781 M2P_IsoDetfunctionStatus_05 0 "无效" 1 "绝缘检测功能关闭" 2 "绝缘检测功能开启" ;
VAL_ 2332421781 M2P_TMS_Address_infor_05 0 "invalid" 1 "TMS1" 2 "TMS2" ;
VAL_ 2332421782 M2P_TMSCalibration_06 1 "仅管理TMS1（第1个电柜开始）" 3 "仅管理TMS2（第1个电柜开始）" ;
VAL_ 2332421782 M2P_IsoDetfunctionStatus_06 0 "无效" 1 "绝缘检测功能关闭" 2 "绝缘检测功能开启" ;
VAL_ 2332421782 M2P_TMS_Address_infor_06 0 "invalid" 1 "TMS1" 2 "TMS2" ;
VAL_ 2332421783 M2P_TMSCalibration_07 1 "仅管理TMS1（第1个电柜开始）" 3 "仅管理TMS2（第1个电柜开始）" ;
VAL_ 2332421783 M2P_IsoDetfunctionStatus_07 0 "无效" 1 "绝缘检测功能关闭" 2 "绝缘检测功能开启" ;
VAL_ 2332421783 M2P_TMS_Address_infor_07 0 "invalid" 1 "TMS1" 2 "TMS2" ;
VAL_ 2332421784 M2P_TMSCalibration_08 1 "仅管理TMS1（第1个电柜开始）" 3 "仅管理TMS2（第1个电柜开始）" ;
VAL_ 2332421784 M2P_IsoDetfunctionStatus_08 0 "无效" 1 "绝缘检测功能关闭" 2 "绝缘检测功能开启" ;
VAL_ 2332421784 M2P_TMS_Address_infor_08 0 "invalid" 1 "TMS1" 2 "TMS2" ;
VAL_ 2332421785 M2P_TMSCalibration_09 1 "仅管理TMS1（第1个电柜开始）" 3 "仅管理TMS2（第1个电柜开始）" ;
VAL_ 2332421785 M2P_IsoDetfunctionStatus_09 0 "无效" 1 "绝缘检测功能关闭" 2 "绝缘检测功能开启" ;
VAL_ 2332421785 M2P_TMS_Address_infor_09 0 "invalid" 1 "TMS1" 2 "TMS2" ;
VAL_ 2332421786 M2P_TMSCalibration_10 1 "仅管理TMS1（第1个电柜开始）" 3 "仅管理TMS2（第1个电柜开始）" ;
VAL_ 2332421786 M2P_IsoDetfunctionStatus_10 0 "无效" 1 "绝缘检测功能关闭" 2 "绝缘检测功能开启" ;
VAL_ 2332421786 M2P_TMS_Address_infor_10 0 "invalid" 1 "TMS1" 2 "TMS2" ;
VAL_ 2332421787 M2P_TMSCalibration_11 1 "仅管理TMS1（第1个电柜开始）" 3 "仅管理TMS2（第1个电柜开始）" ;
VAL_ 2332421787 M2P_IsoDetfunctionStatus_11 0 "无效" 1 "绝缘检测功能关闭" 2 "绝缘检测功能开启" ;
VAL_ 2332421787 M2P_TMS_Address_infor_11 0 "invalid" 1 "TMS1" 2 "TMS2" ;
VAL_ 2332421788 M2P_TMSCalibration_12 1 "仅管理TMS1（第1个电柜开始）" 3 "仅管理TMS2（第1个电柜开始）" ;
VAL_ 2332421788 M2P_IsoDetfunctionStatus_12 0 "无效" 1 "绝缘检测功能关闭" 2 "绝缘检测功能开启" ;
VAL_ 2332421788 M2P_TMS_Address_infor_12 0 "invalid" 1 "TMS1" 2 "TMS2" ;
VAL_ 2332421789 M2P_TMSCalibration_13 1 "仅管理TMS1（第1个电柜开始）" 3 "仅管理TMS2（第1个电柜开始）" ;
VAL_ 2332421789 M2P_IsoDetfunctionStatus_13 0 "无效" 1 "绝缘检测功能关闭" 2 "绝缘检测功能开启" ;
VAL_ 2332421789 M2P_TMS_Address_infor_13 0 "invalid" 1 "TMS1" 2 "TMS2" ;
VAL_ 2332421790 M2P_TMSCalibration_14 1 "仅管理TMS1（第1个电柜开始）" 3 "仅管理TMS2（第1个电柜开始）" ;
VAL_ 2332421790 M2P_IsoDetfunctionStatus_14 0 "无效" 1 "绝缘检测功能关闭" 2 "绝缘检测功能开启" ;
VAL_ 2332421790 M2P_TMS_Address_infor_14 0 "invalid" 1 "TMS1" 2 "TMS2" ;
VAL_ 2332421791 M2P_TMSCalibration_15 1 "仅管理TMS1（第1个电柜开始）" 3 "仅管理TMS2（第1个电柜开始）" ;
VAL_ 2332421791 M2P_IsoDetfunctionStatus_15 0 "无效" 1 "绝缘检测功能关闭" 2 "绝缘检测功能开启" ;
VAL_ 2332421791 M2P_TMS_Address_infor_15 0 "invalid" 1 "TMS1" 2 "TMS2" ;
VAL_ 2332421792 M2P_TMSCalibration_16 1 "仅管理TMS1（第1个电柜开始）" 3 "仅管理TMS2（第1个电柜开始）" ;
VAL_ 2332421792 M2P_IsoDetfunctionStatus_16 0 "无效" 1 "绝缘检测功能关闭" 2 "绝缘检测功能开启" ;
VAL_ 2332421792 M2P_TMS_Address_infor_16 0 "invalid" 1 "TMS1" 2 "TMS2" ;
VAL_ 2332421793 M2P_TMSCalibration_17 1 "仅管理TMS1（第1个电柜开始）" 3 "仅管理TMS2（第1个电柜开始）" ;
VAL_ 2332421793 M2P_IsoDetfunctionStatus_17 0 "无效" 1 "绝缘检测功能关闭" 2 "绝缘检测功能开启" ;
VAL_ 2332421793 M2P_TMS_Address_infor_17 0 "invalid" 1 "TMS1" 2 "TMS2" ;
VAL_ 2332421794 M2P_TMSCalibration_18 1 "仅管理TMS1（第1个电柜开始）" 3 "仅管理TMS2（第1个电柜开始）" ;
VAL_ 2332421794 M2P_IsoDetfunctionStatus_18 0 "无效" 1 "绝缘检测功能关闭" 2 "绝缘检测功能开启" ;
VAL_ 2332421794 M2P_TMS_Address_infor_18 0 "invalid" 1 "TMS1" 2 "TMS2" ;
VAL_ 2332421795 M2P_TMSCalibration_19 1 "仅管理TMS1（第1个电柜开始）" 3 "仅管理TMS2（第1个电柜开始）" ;
VAL_ 2332421795 M2P_IsoDetfunctionStatus_19 0 "无效" 1 "绝缘检测功能关闭" 2 "绝缘检测功能开启" ;
VAL_ 2332421795 M2P_TMS_Address_infor_19 0 "invalid" 1 "TMS1" 2 "TMS2" ;
VAL_ 2332421796 M2P_TMSCalibration_20 1 "仅管理TMS1（第1个电柜开始）" 3 "仅管理TMS2（第1个电柜开始）" ;
VAL_ 2332421796 M2P_IsoDetfunctionStatus_20 0 "无效" 1 "绝缘检测功能关闭" 2 "绝缘检测功能开启" ;
VAL_ 2332421796 M2P_TMS_Address_infor_20 0 "invalid" 1 "TMS1" 2 "TMS2" ;
VAL_ 2332421797 M2P_TMSCalibration_21 1 "仅管理TMS1（第1个电柜开始）" 3 "仅管理TMS2（第1个电柜开始）" ;
VAL_ 2332421797 M2P_IsoDetfunctionStatus_21 0 "无效" 1 "绝缘检测功能关闭" 2 "绝缘检测功能开启" ;
VAL_ 2332421797 M2P_TMS_Address_infor_21 0 "invalid" 1 "TMS1" 2 "TMS2" ;
VAL_ 2332421798 M2P_TMSCalibration_22 1 "仅管理TMS1（第1个电柜开始）" 3 "仅管理TMS2（第1个电柜开始）" ;
VAL_ 2332421798 M2P_IsoDetfunctionStatus_22 0 "无效" 1 "绝缘检测功能关闭" 2 "绝缘检测功能开启" ;
VAL_ 2332421798 M2P_TMS_Address_infor_22 0 "invalid" 1 "TMS1" 2 "TMS2" ;
VAL_ 2332421799 M2P_TMSCalibration_23 1 "仅管理TMS1（第1个电柜开始）" 3 "仅管理TMS2（第1个电柜开始）" ;
VAL_ 2332421799 M2P_IsoDetfunctionStatus_23 0 "无效" 1 "绝缘检测功能关闭" 2 "绝缘检测功能开启" ;
VAL_ 2332421799 M2P_TMS_Address_infor_23 0 "invalid" 1 "TMS1" 2 "TMS2" ;
VAL_ 2332421800 M2P_TMSCalibration_24 1 "仅管理TMS1（第1个电柜开始）" 3 "仅管理TMS2（第1个电柜开始）" ;
VAL_ 2332421800 M2P_IsoDetfunctionStatus_24 0 "无效" 1 "绝缘检测功能关闭" 2 "绝缘检测功能开启" ;
VAL_ 2332421800 M2P_TMS_Address_infor_24 0 "invalid" 1 "TMS1" 2 "TMS2" ;
VAL_ 2332421801 M2P_TMSCalibration_25 1 "仅管理TMS1（第1个电柜开始）" 3 "仅管理TMS2（第1个电柜开始）" ;
VAL_ 2332421801 M2P_IsoDetfunctionStatus_25 0 "无效" 1 "绝缘检测功能关闭" 2 "绝缘检测功能开启" ;
VAL_ 2332421801 M2P_TMS_Address_infor_25 0 "invalid" 1 "TMS1" 2 "TMS2" ;
VAL_ 2332421802 M2P_TMSCalibration_26 1 "仅管理TMS1（第1个电柜开始）" 3 "仅管理TMS2（第1个电柜开始）" ;
VAL_ 2332421802 M2P_IsoDetfunctionStatus_26 0 "无效" 1 "绝缘检测功能关闭" 2 "绝缘检测功能开启" ;
VAL_ 2332421802 M2P_TMS_Address_infor_26 0 "invalid" 1 "TMS1" 2 "TMS2" ;
VAL_ 2332421803 M2P_TMSCalibration_27 1 "仅管理TMS1（第1个电柜开始）" 3 "仅管理TMS2（第1个电柜开始）" ;
VAL_ 2332421803 M2P_IsoDetfunctionStatus_27 0 "无效" 1 "绝缘检测功能关闭" 2 "绝缘检测功能开启" ;
VAL_ 2332421803 M2P_TMS_Address_infor_27 0 "invalid" 1 "TMS1" 2 "TMS2" ;
VAL_ 2332421804 M2P_TMSCalibration_28 1 "仅管理TMS1（第1个电柜开始）" 3 "仅管理TMS2（第1个电柜开始）" ;
VAL_ 2332421804 M2P_IsoDetfunctionStatus_28 0 "无效" 1 "绝缘检测功能关闭" 2 "绝缘检测功能开启" ;
VAL_ 2332421804 M2P_TMS_Address_infor_28 0 "invalid" 1 "TMS1" 2 "TMS2" ;
VAL_ 2332421805 M2P_TMSCalibration_29 1 "仅管理TMS1（第1个电柜开始）" 3 "仅管理TMS2（第1个电柜开始）" ;
VAL_ 2332421805 M2P_IsoDetfunctionStatus_29 0 "无效" 1 "绝缘检测功能关闭" 2 "绝缘检测功能开启" ;
VAL_ 2332421805 M2P_TMS_Address_infor_29 0 "invalid" 1 "TMS1" 2 "TMS2" ;
VAL_ 2332421806 M2P_TMSCalibration_30 1 "仅管理TMS1（第1个电柜开始）" 3 "仅管理TMS2（第1个电柜开始）" ;
VAL_ 2332421806 M2P_IsoDetfunctionStatus_30 0 "无效" 1 "绝缘检测功能关闭" 2 "绝缘检测功能开启" ;
VAL_ 2332421806 M2P_TMS_Address_infor_30 0 "invalid" 1 "TMS1" 2 "TMS2" ;
VAL_ 2332421807 M2P_TMSCalibration_31 1 "仅管理TMS1（第1个电柜开始）" 3 "仅管理TMS2（第1个电柜开始）" ;
VAL_ 2332421807 M2P_IsoDetfunctionStatus_31 0 "无效" 1 "绝缘检测功能关闭" 2 "绝缘检测功能开启" ;
VAL_ 2332421807 M2P_TMS_Address_infor_31 0 "invalid" 1 "TMS1" 2 "TMS2" ;
VAL_ 2332487313 M2P_StepChrMode_01 0 "Disable" 1 "Enable" 2 "Invalid" 3 "Default" ;
VAL_ 2332487313 M2P_BUS1_HVState_01 0 "Bus Power off" 1 "Bus Power on" ;
VAL_ 2332487313 M2P_BUS2_HVState_01 0 "Bus Power off" 1 "Bus Power on" ;
VAL_ 2332487313 M2P_BUS3_HVState_01 0 "Bus Power off" 1 "Bus Power on" ;
VAL_ 2332487313 M2P_BUS4_HVState_01 0 "Bus Power off" 1 "Bus Power on" ;
VAL_ 2332487313 M2P_BUS5_HVState_01 0 "Bus Power off" 1 "Bus Power on" ;
VAL_ 2332487313 M2P_BUS6_HVState_01 0 "Bus Power off" 1 "Bus Power on" ;
VAL_ 2332487313 M2P_BUS7_HVState_01 0 "Bus Power off" 1 "Bus Power on" ;
VAL_ 2332487313 M2P_BUS8_HVState_01 0 "Bus Power off" 1 "Bus Power on" ;
VAL_ 2332487313 M2P_BUS9_HVState_01 0 "Bus Power off" 1 "Bus Power on" ;
VAL_ 2332487313 M2P_BUS10_HVState_01 0 "Bus Power off" 1 "Bus Power on" ;
VAL_ 2332487313 M2P_BUS11_HVState_01 0 "Bus Power off" 1 "Bus Power on" ;
VAL_ 2332487313 M2P_BUS12_HVState_01 0 "Bus Power off" 1 "Bus Power on" ;
VAL_ 2332487314 M2P_StepChrMode_02 0 "Disable" 1 "Enable" 2 "Invalid" 3 "Default" ;
VAL_ 2332487314 M2P_BUS1_HVState_02 0 "Bus Power off" 1 "Bus Power on" ;
VAL_ 2332487314 M2P_BUS2_HVState_02 0 "Bus Power off" 1 "Bus Power on" ;
VAL_ 2332487314 M2P_BUS3_HVState_02 0 "Bus Power off" 1 "Bus Power on" ;
VAL_ 2332487314 M2P_BUS4_HVState_02 0 "Bus Power off" 1 "Bus Power on" ;
VAL_ 2332487314 M2P_BUS5_HVState_02 0 "Bus Power off" 1 "Bus Power on" ;
VAL_ 2332487314 M2P_BUS6_HVState_02 0 "Bus Power off" 1 "Bus Power on" ;
VAL_ 2332487314 M2P_BUS7_HVState_02 0 "Bus Power off" 1 "Bus Power on" ;
VAL_ 2332487314 M2P_BUS8_HVState_02 0 "Bus Power off" 1 "Bus Power on" ;
VAL_ 2332487314 M2P_BUS9_HVState_02 0 "Bus Power off" 1 "Bus Power on" ;
VAL_ 2332487314 M2P_BUS10_HVState_02 0 "Bus Power off" 1 "Bus Power on" ;
VAL_ 2332487314 M2P_BUS11_HVState_02 0 "Bus Power off" 1 "Bus Power on" ;
VAL_ 2332487314 M2P_BUS12_HVState_02 0 "Bus Power off" 1 "Bus Power on" ;
VAL_ 2332487315 M2P_StepChrMode_03 0 "Disable" 1 "Enable" 2 "Invalid" 3 "Default" ;
VAL_ 2332487315 M2P_BUS1_HVState_03 0 "Bus Power off" 1 "Bus Power on" ;
VAL_ 2332487315 M2P_BUS2_HVState_03 0 "Bus Power off" 1 "Bus Power on" ;
VAL_ 2332487315 M2P_BUS3_HVState_03 0 "Bus Power off" 1 "Bus Power on" ;
VAL_ 2332487315 M2P_BUS4_HVState_03 0 "Bus Power off" 1 "Bus Power on" ;
VAL_ 2332487315 M2P_BUS5_HVState_03 0 "Bus Power off" 1 "Bus Power on" ;
VAL_ 2332487315 M2P_BUS6_HVState_03 0 "Bus Power off" 1 "Bus Power on" ;
VAL_ 2332487315 M2P_BUS7_HVState_03 0 "Bus Power off" 1 "Bus Power on" ;
VAL_ 2332487315 M2P_BUS8_HVState_03 0 "Bus Power off" 1 "Bus Power on" ;
VAL_ 2332487315 M2P_BUS9_HVState_03 0 "Bus Power off" 1 "Bus Power on" ;
VAL_ 2332487315 M2P_BUS10_HVState_03 0 "Bus Power off" 1 "Bus Power on" ;
VAL_ 2332487315 M2P_BUS11_HVState_03 0 "Bus Power off" 1 "Bus Power on" ;
VAL_ 2332487315 M2P_BUS12_HVState_03 0 "Bus Power off" 1 "Bus Power on" ;
VAL_ 2332487316 M2P_StepChrMode_04 0 "Disable" 1 "Enable" 2 "Invalid" 3 "Default" ;
VAL_ 2332487316 M2P_BUS1_HVState_04 0 "Bus Power off" 1 "Bus Power on" ;
VAL_ 2332487316 M2P_BUS2_HVState_04 0 "Bus Power off" 1 "Bus Power on" ;
VAL_ 2332487316 M2P_BUS3_HVState_04 0 "Bus Power off" 1 "Bus Power on" ;
VAL_ 2332487316 M2P_BUS4_HVState_04 0 "Bus Power off" 1 "Bus Power on" ;
VAL_ 2332487316 M2P_BUS5_HVState_04 0 "Bus Power off" 1 "Bus Power on" ;
VAL_ 2332487316 M2P_BUS6_HVState_04 0 "Bus Power off" 1 "Bus Power on" ;
VAL_ 2332487316 M2P_BUS7_HVState_04 0 "Bus Power off" 1 "Bus Power on" ;
VAL_ 2332487316 M2P_BUS8_HVState_04 0 "Bus Power off" 1 "Bus Power on" ;
VAL_ 2332487316 M2P_BUS9_HVState_04 0 "Bus Power off" 1 "Bus Power on" ;
VAL_ 2332487316 M2P_BUS10_HVState_04 0 "Bus Power off" 1 "Bus Power on" ;
VAL_ 2332487316 M2P_BUS11_HVState_04 0 "Bus Power off" 1 "Bus Power on" ;
VAL_ 2332487316 M2P_BUS12_HVState_04 0 "Bus Power off" 1 "Bus Power on" ;
VAL_ 2332487317 M2P_StepChrMode_05 0 "Disable" 1 "Enable" 2 "Invalid" 3 "Default" ;
VAL_ 2332487317 M2P_BUS1_HVState_05 0 "Bus Power off" 1 "Bus Power on" ;
VAL_ 2332487317 M2P_BUS2_HVState_05 0 "Bus Power off" 1 "Bus Power on" ;
VAL_ 2332487317 M2P_BUS3_HVState_05 0 "Bus Power off" 1 "Bus Power on" ;
VAL_ 2332487317 M2P_BUS4_HVState_05 0 "Bus Power off" 1 "Bus Power on" ;
VAL_ 2332487317 M2P_BUS5_HVState_05 0 "Bus Power off" 1 "Bus Power on" ;
VAL_ 2332487317 M2P_BUS6_HVState_05 0 "Bus Power off" 1 "Bus Power on" ;
VAL_ 2332487317 M2P_BUS7_HVState_05 0 "Bus Power off" 1 "Bus Power on" ;
VAL_ 2332487317 M2P_BUS8_HVState_05 0 "Bus Power off" 1 "Bus Power on" ;
VAL_ 2332487317 M2P_BUS9_HVState_05 0 "Bus Power off" 1 "Bus Power on" ;
VAL_ 2332487317 M2P_BUS10_HVState_05 0 "Bus Power off" 1 "Bus Power on" ;
VAL_ 2332487317 M2P_BUS11_HVState_05 0 "Bus Power off" 1 "Bus Power on" ;
VAL_ 2332487317 M2P_BUS12_HVState_05 0 "Bus Power off" 1 "Bus Power on" ;
VAL_ 2332487318 M2P_StepChrMode_06 0 "Disable" 1 "Enable" 2 "Invalid" 3 "Default" ;
VAL_ 2332487318 M2P_BUS1_HVState_06 0 "Bus Power off" 1 "Bus Power on" ;
VAL_ 2332487318 M2P_BUS2_HVState_06 0 "Bus Power off" 1 "Bus Power on" ;
VAL_ 2332487318 M2P_BUS3_HVState_06 0 "Bus Power off" 1 "Bus Power on" ;
VAL_ 2332487318 M2P_BUS4_HVState_06 0 "Bus Power off" 1 "Bus Power on" ;
VAL_ 2332487318 M2P_BUS5_HVState_06 0 "Bus Power off" 1 "Bus Power on" ;
VAL_ 2332487318 M2P_BUS6_HVState_06 0 "Bus Power off" 1 "Bus Power on" ;
VAL_ 2332487318 M2P_BUS7_HVState_06 0 "Bus Power off" 1 "Bus Power on" ;
VAL_ 2332487318 M2P_BUS8_HVState_06 0 "Bus Power off" 1 "Bus Power on" ;
VAL_ 2332487318 M2P_BUS9_HVState_06 0 "Bus Power off" 1 "Bus Power on" ;
VAL_ 2332487318 M2P_BUS10_HVState_06 0 "Bus Power off" 1 "Bus Power on" ;
VAL_ 2332487318 M2P_BUS11_HVState_06 0 "Bus Power off" 1 "Bus Power on" ;
VAL_ 2332487318 M2P_BUS12_HVState_06 0 "Bus Power off" 1 "Bus Power on" ;
VAL_ 2332487319 M2P_StepChrMode_07 0 "Disable" 1 "Enable" 2 "Invalid" 3 "Default" ;
VAL_ 2332487319 M2P_BUS1_HVState_07 0 "Bus Power off" 1 "Bus Power on" ;
VAL_ 2332487319 M2P_BUS2_HVState_07 0 "Bus Power off" 1 "Bus Power on" ;
VAL_ 2332487319 M2P_BUS3_HVState_07 0 "Bus Power off" 1 "Bus Power on" ;
VAL_ 2332487319 M2P_BUS4_HVState_07 0 "Bus Power off" 1 "Bus Power on" ;
VAL_ 2332487319 M2P_BUS5_HVState_07 0 "Bus Power off" 1 "Bus Power on" ;
VAL_ 2332487319 M2P_BUS6_HVState_07 0 "Bus Power off" 1 "Bus Power on" ;
VAL_ 2332487319 M2P_BUS7_HVState_07 0 "Bus Power off" 1 "Bus Power on" ;
VAL_ 2332487319 M2P_BUS8_HVState_07 0 "Bus Power off" 1 "Bus Power on" ;
VAL_ 2332487319 M2P_BUS9_HVState_07 0 "Bus Power off" 1 "Bus Power on" ;
VAL_ 2332487319 M2P_BUS10_HVState_07 0 "Bus Power off" 1 "Bus Power on" ;
VAL_ 2332487319 M2P_BUS11_HVState_07 0 "Bus Power off" 1 "Bus Power on" ;
VAL_ 2332487319 M2P_BUS12_HVState_07 0 "Bus Power off" 1 "Bus Power on" ;
VAL_ 2332487320 M2P_StepChrMode_08 0 "Disable" 1 "Enable" 2 "Invalid" 3 "Default" ;
VAL_ 2332487320 M2P_BUS1_HVState_08 0 "Bus Power off" 1 "Bus Power on" ;
VAL_ 2332487320 M2P_BUS2_HVState_08 0 "Bus Power off" 1 "Bus Power on" ;
VAL_ 2332487320 M2P_BUS3_HVState_08 0 "Bus Power off" 1 "Bus Power on" ;
VAL_ 2332487320 M2P_BUS4_HVState_08 0 "Bus Power off" 1 "Bus Power on" ;
VAL_ 2332487320 M2P_BUS5_HVState_08 0 "Bus Power off" 1 "Bus Power on" ;
VAL_ 2332487320 M2P_BUS6_HVState_08 0 "Bus Power off" 1 "Bus Power on" ;
VAL_ 2332487320 M2P_BUS7_HVState_08 0 "Bus Power off" 1 "Bus Power on" ;
VAL_ 2332487320 M2P_BUS8_HVState_08 0 "Bus Power off" 1 "Bus Power on" ;
VAL_ 2332487320 M2P_BUS9_HVState_08 0 "Bus Power off" 1 "Bus Power on" ;
VAL_ 2332487320 M2P_BUS10_HVState_08 0 "Bus Power off" 1 "Bus Power on" ;
VAL_ 2332487320 M2P_BUS11_HVState_08 0 "Bus Power off" 1 "Bus Power on" ;
VAL_ 2332487320 M2P_BUS12_HVState_08 0 "Bus Power off" 1 "Bus Power on" ;
VAL_ 2332487321 M2P_StepChrMode_09 0 "Disable" 1 "Enable" 2 "Invalid" 3 "Default" ;
VAL_ 2332487321 M2P_BUS1_HVState_09 0 "Bus Power off" 1 "Bus Power on" ;
VAL_ 2332487321 M2P_BUS2_HVState_09 0 "Bus Power off" 1 "Bus Power on" ;
VAL_ 2332487321 M2P_BUS3_HVState_09 0 "Bus Power off" 1 "Bus Power on" ;
VAL_ 2332487321 M2P_BUS4_HVState_09 0 "Bus Power off" 1 "Bus Power on" ;
VAL_ 2332487321 M2P_BUS5_HVState_09 0 "Bus Power off" 1 "Bus Power on" ;
VAL_ 2332487321 M2P_BUS6_HVState_09 0 "Bus Power off" 1 "Bus Power on" ;
VAL_ 2332487321 M2P_BUS7_HVState_09 0 "Bus Power off" 1 "Bus Power on" ;
VAL_ 2332487321 M2P_BUS8_HVState_09 0 "Bus Power off" 1 "Bus Power on" ;
VAL_ 2332487321 M2P_BUS9_HVState_09 0 "Bus Power off" 1 "Bus Power on" ;
VAL_ 2332487321 M2P_BUS10_HVState_09 0 "Bus Power off" 1 "Bus Power on" ;
VAL_ 2332487321 M2P_BUS11_HVState_09 0 "Bus Power off" 1 "Bus Power on" ;
VAL_ 2332487321 M2P_BUS12_HVState_09 0 "Bus Power off" 1 "Bus Power on" ;
VAL_ 2332487322 M2P_StepChrMode_10 0 "Disable" 1 "Enable" 2 "Invalid" 3 "Default" ;
VAL_ 2332487322 M2P_BUS1_HVState_10 0 "Bus Power off" 1 "Bus Power on" ;
VAL_ 2332487322 M2P_BUS2_HVState_10 0 "Bus Power off" 1 "Bus Power on" ;
VAL_ 2332487322 M2P_BUS3_HVState_10 0 "Bus Power off" 1 "Bus Power on" ;
VAL_ 2332487322 M2P_BUS4_HVState_10 0 "Bus Power off" 1 "Bus Power on" ;
VAL_ 2332487322 M2P_BUS5_HVState_10 0 "Bus Power off" 1 "Bus Power on" ;
VAL_ 2332487322 M2P_BUS6_HVState_10 0 "Bus Power off" 1 "Bus Power on" ;
VAL_ 2332487322 M2P_BUS7_HVState_10 0 "Bus Power off" 1 "Bus Power on" ;
VAL_ 2332487322 M2P_BUS8_HVState_10 0 "Bus Power off" 1 "Bus Power on" ;
VAL_ 2332487322 M2P_BUS9_HVState_10 0 "Bus Power off" 1 "Bus Power on" ;
VAL_ 2332487322 M2P_BUS10_HVState_10 0 "Bus Power off" 1 "Bus Power on" ;
VAL_ 2332487322 M2P_BUS11_HVState_10 0 "Bus Power off" 1 "Bus Power on" ;
VAL_ 2332487322 M2P_BUS12_HVState_10 0 "Bus Power off" 1 "Bus Power on" ;
VAL_ 2332487323 M2P_StepChrMode_11 0 "Disable" 1 "Enable" 2 "Invalid" 3 "Default" ;
VAL_ 2332487323 M2P_BUS1_HVState_11 0 "Bus Power off" 1 "Bus Power on" ;
VAL_ 2332487323 M2P_BUS2_HVState_11 0 "Bus Power off" 1 "Bus Power on" ;
VAL_ 2332487323 M2P_BUS3_HVState_11 0 "Bus Power off" 1 "Bus Power on" ;
VAL_ 2332487323 M2P_BUS4_HVState_11 0 "Bus Power off" 1 "Bus Power on" ;
VAL_ 2332487323 M2P_BUS5_HVState_11 0 "Bus Power off" 1 "Bus Power on" ;
VAL_ 2332487323 M2P_BUS6_HVState_11 0 "Bus Power off" 1 "Bus Power on" ;
VAL_ 2332487323 M2P_BUS7_HVState_11 0 "Bus Power off" 1 "Bus Power on" ;
VAL_ 2332487323 M2P_BUS8_HVState_11 0 "Bus Power off" 1 "Bus Power on" ;
VAL_ 2332487323 M2P_BUS9_HVState_11 0 "Bus Power off" 1 "Bus Power on" ;
VAL_ 2332487323 M2P_BUS10_HVState_11 0 "Bus Power off" 1 "Bus Power on" ;
VAL_ 2332487323 M2P_BUS11_HVState_11 0 "Bus Power off" 1 "Bus Power on" ;
VAL_ 2332487323 M2P_BUS12_HVState_11 0 "Bus Power off" 1 "Bus Power on" ;
VAL_ 2332487324 M2P_StepChrMode_12 0 "Disable" 1 "Enable" 2 "Invalid" 3 "Default" ;
VAL_ 2332487324 M2P_BUS1_HVState_12 0 "Bus Power off" 1 "Bus Power on" ;
VAL_ 2332487324 M2P_BUS2_HVState_12 0 "Bus Power off" 1 "Bus Power on" ;
VAL_ 2332487324 M2P_BUS3_HVState_12 0 "Bus Power off" 1 "Bus Power on" ;
VAL_ 2332487324 M2P_BUS4_HVState_12 0 "Bus Power off" 1 "Bus Power on" ;
VAL_ 2332487324 M2P_BUS5_HVState_12 0 "Bus Power off" 1 "Bus Power on" ;
VAL_ 2332487324 M2P_BUS6_HVState_12 0 "Bus Power off" 1 "Bus Power on" ;
VAL_ 2332487324 M2P_BUS7_HVState_12 0 "Bus Power off" 1 "Bus Power on" ;
VAL_ 2332487324 M2P_BUS8_HVState_12 0 "Bus Power off" 1 "Bus Power on" ;
VAL_ 2332487324 M2P_BUS9_HVState_12 0 "Bus Power off" 1 "Bus Power on" ;
VAL_ 2332487324 M2P_BUS10_HVState_12 0 "Bus Power off" 1 "Bus Power on" ;
VAL_ 2332487324 M2P_BUS11_HVState_12 0 "Bus Power off" 1 "Bus Power on" ;
VAL_ 2332487324 M2P_BUS12_HVState_12 0 "Bus Power off" 1 "Bus Power on" ;
VAL_ 2332487325 M2P_StepChrMode_13 0 "Disable" 1 "Enable" 2 "Invalid" 3 "Default" ;
VAL_ 2332487325 M2P_BUS1_HVState_13 0 "Bus Power off" 1 "Bus Power on" ;
VAL_ 2332487325 M2P_BUS2_HVState_13 0 "Bus Power off" 1 "Bus Power on" ;
VAL_ 2332487325 M2P_BUS3_HVState_13 0 "Bus Power off" 1 "Bus Power on" ;
VAL_ 2332487325 M2P_BUS4_HVState_13 0 "Bus Power off" 1 "Bus Power on" ;
VAL_ 2332487325 M2P_BUS5_HVState_13 0 "Bus Power off" 1 "Bus Power on" ;
VAL_ 2332487325 M2P_BUS6_HVState_13 0 "Bus Power off" 1 "Bus Power on" ;
VAL_ 2332487325 M2P_BUS7_HVState_13 0 "Bus Power off" 1 "Bus Power on" ;
VAL_ 2332487325 M2P_BUS8_HVState_13 0 "Bus Power off" 1 "Bus Power on" ;
VAL_ 2332487325 M2P_BUS9_HVState_13 0 "Bus Power off" 1 "Bus Power on" ;
VAL_ 2332487325 M2P_BUS10_HVState_13 0 "Bus Power off" 1 "Bus Power on" ;
VAL_ 2332487325 M2P_BUS11_HVState_13 0 "Bus Power off" 1 "Bus Power on" ;
VAL_ 2332487325 M2P_BUS12_HVState_13 0 "Bus Power off" 1 "Bus Power on" ;
VAL_ 2332487326 M2P_StepChrMode_14 0 "Disable" 1 "Enable" 2 "Invalid" 3 "Default" ;
VAL_ 2332487326 M2P_BUS1_HVState_14 0 "Bus Power off" 1 "Bus Power on" ;
VAL_ 2332487326 M2P_BUS2_HVState_14 0 "Bus Power off" 1 "Bus Power on" ;
VAL_ 2332487326 M2P_BUS3_HVState_14 0 "Bus Power off" 1 "Bus Power on" ;
VAL_ 2332487326 M2P_BUS4_HVState_14 0 "Bus Power off" 1 "Bus Power on" ;
VAL_ 2332487326 M2P_BUS5_HVState_14 0 "Bus Power off" 1 "Bus Power on" ;
VAL_ 2332487326 M2P_BUS6_HVState_14 0 "Bus Power off" 1 "Bus Power on" ;
VAL_ 2332487326 M2P_BUS7_HVState_14 0 "Bus Power off" 1 "Bus Power on" ;
VAL_ 2332487326 M2P_BUS8_HVState_14 0 "Bus Power off" 1 "Bus Power on" ;
VAL_ 2332487326 M2P_BUS9_HVState_14 0 "Bus Power off" 1 "Bus Power on" ;
VAL_ 2332487326 M2P_BUS10_HVState_14 0 "Bus Power off" 1 "Bus Power on" ;
VAL_ 2332487326 M2P_BUS11_HVState_14 0 "Bus Power off" 1 "Bus Power on" ;
VAL_ 2332487326 M2P_BUS12_HVState_14 0 "Bus Power off" 1 "Bus Power on" ;
VAL_ 2332487327 M2P_StepChrMode_15 0 "Disable" 1 "Enable" 2 "Invalid" 3 "Default" ;
VAL_ 2332487327 M2P_BUS1_HVState_15 0 "Bus Power off" 1 "Bus Power on" ;
VAL_ 2332487327 M2P_BUS2_HVState_15 0 "Bus Power off" 1 "Bus Power on" ;
VAL_ 2332487327 M2P_BUS3_HVState_15 0 "Bus Power off" 1 "Bus Power on" ;
VAL_ 2332487327 M2P_BUS4_HVState_15 0 "Bus Power off" 1 "Bus Power on" ;
VAL_ 2332487327 M2P_BUS5_HVState_15 0 "Bus Power off" 1 "Bus Power on" ;
VAL_ 2332487327 M2P_BUS6_HVState_15 0 "Bus Power off" 1 "Bus Power on" ;
VAL_ 2332487327 M2P_BUS7_HVState_15 0 "Bus Power off" 1 "Bus Power on" ;
VAL_ 2332487327 M2P_BUS8_HVState_15 0 "Bus Power off" 1 "Bus Power on" ;
VAL_ 2332487327 M2P_BUS9_HVState_15 0 "Bus Power off" 1 "Bus Power on" ;
VAL_ 2332487327 M2P_BUS10_HVState_15 0 "Bus Power off" 1 "Bus Power on" ;
VAL_ 2332487327 M2P_BUS11_HVState_15 0 "Bus Power off" 1 "Bus Power on" ;
VAL_ 2332487327 M2P_BUS12_HVState_15 0 "Bus Power off" 1 "Bus Power on" ;
VAL_ 2332487328 M2P_StepChrMode_16 0 "Disable" 1 "Enable" 2 "Invalid" 3 "Default" ;
VAL_ 2332487328 M2P_BUS1_HVState_16 0 "Bus Power off" 1 "Bus Power on" ;
VAL_ 2332487328 M2P_BUS2_HVState_16 0 "Bus Power off" 1 "Bus Power on" ;
VAL_ 2332487328 M2P_BUS3_HVState_16 0 "Bus Power off" 1 "Bus Power on" ;
VAL_ 2332487328 M2P_BUS4_HVState_16 0 "Bus Power off" 1 "Bus Power on" ;
VAL_ 2332487328 M2P_BUS5_HVState_16 0 "Bus Power off" 1 "Bus Power on" ;
VAL_ 2332487328 M2P_BUS6_HVState_16 0 "Bus Power off" 1 "Bus Power on" ;
VAL_ 2332487328 M2P_BUS7_HVState_16 0 "Bus Power off" 1 "Bus Power on" ;
VAL_ 2332487328 M2P_BUS8_HVState_16 0 "Bus Power off" 1 "Bus Power on" ;
VAL_ 2332487328 M2P_BUS9_HVState_16 0 "Bus Power off" 1 "Bus Power on" ;
VAL_ 2332487328 M2P_BUS10_HVState_16 0 "Bus Power off" 1 "Bus Power on" ;
VAL_ 2332487328 M2P_BUS11_HVState_16 0 "Bus Power off" 1 "Bus Power on" ;
VAL_ 2332487328 M2P_BUS12_HVState_16 0 "Bus Power off" 1 "Bus Power on" ;
VAL_ 2332487329 M2P_StepChrMode_17 0 "Disable" 1 "Enable" 2 "Invalid" 3 "Default" ;
VAL_ 2332487329 M2P_BUS1_HVState_17 0 "Bus Power off" 1 "Bus Power on" ;
VAL_ 2332487329 M2P_BUS2_HVState_17 0 "Bus Power off" 1 "Bus Power on" ;
VAL_ 2332487329 M2P_BUS3_HVState_17 0 "Bus Power off" 1 "Bus Power on" ;
VAL_ 2332487329 M2P_BUS4_HVState_17 0 "Bus Power off" 1 "Bus Power on" ;
VAL_ 2332487329 M2P_BUS5_HVState_17 0 "Bus Power off" 1 "Bus Power on" ;
VAL_ 2332487329 M2P_BUS6_HVState_17 0 "Bus Power off" 1 "Bus Power on" ;
VAL_ 2332487329 M2P_BUS7_HVState_17 0 "Bus Power off" 1 "Bus Power on" ;
VAL_ 2332487329 M2P_BUS8_HVState_17 0 "Bus Power off" 1 "Bus Power on" ;
VAL_ 2332487329 M2P_BUS9_HVState_17 0 "Bus Power off" 1 "Bus Power on" ;
VAL_ 2332487329 M2P_BUS10_HVState_17 0 "Bus Power off" 1 "Bus Power on" ;
VAL_ 2332487329 M2P_BUS11_HVState_17 0 "Bus Power off" 1 "Bus Power on" ;
VAL_ 2332487329 M2P_BUS12_HVState_17 0 "Bus Power off" 1 "Bus Power on" ;
VAL_ 2332487330 M2P_StepChrMode_18 0 "Disable" 1 "Enable" 2 "Invalid" 3 "Default" ;
VAL_ 2332487330 M2P_BUS1_HVState_18 0 "Bus Power off" 1 "Bus Power on" ;
VAL_ 2332487330 M2P_BUS2_HVState_18 0 "Bus Power off" 1 "Bus Power on" ;
VAL_ 2332487330 M2P_BUS3_HVState_18 0 "Bus Power off" 1 "Bus Power on" ;
VAL_ 2332487330 M2P_BUS4_HVState_18 0 "Bus Power off" 1 "Bus Power on" ;
VAL_ 2332487330 M2P_BUS5_HVState_18 0 "Bus Power off" 1 "Bus Power on" ;
VAL_ 2332487330 M2P_BUS6_HVState_18 0 "Bus Power off" 1 "Bus Power on" ;
VAL_ 2332487330 M2P_BUS7_HVState_18 0 "Bus Power off" 1 "Bus Power on" ;
VAL_ 2332487330 M2P_BUS8_HVState_18 0 "Bus Power off" 1 "Bus Power on" ;
VAL_ 2332487330 M2P_BUS9_HVState_18 0 "Bus Power off" 1 "Bus Power on" ;
VAL_ 2332487330 M2P_BUS10_HVState_18 0 "Bus Power off" 1 "Bus Power on" ;
VAL_ 2332487330 M2P_BUS11_HVState_18 0 "Bus Power off" 1 "Bus Power on" ;
VAL_ 2332487330 M2P_BUS12_HVState_18 0 "Bus Power off" 1 "Bus Power on" ;
VAL_ 2332487331 M2P_StepChrMode_19 0 "Disable" 1 "Enable" 2 "Invalid" 3 "Default" ;
VAL_ 2332487331 M2P_BUS1_HVState_19 0 "Bus Power off" 1 "Bus Power on" ;
VAL_ 2332487331 M2P_BUS2_HVState_19 0 "Bus Power off" 1 "Bus Power on" ;
VAL_ 2332487331 M2P_BUS3_HVState_19 0 "Bus Power off" 1 "Bus Power on" ;
VAL_ 2332487331 M2P_BUS4_HVState_19 0 "Bus Power off" 1 "Bus Power on" ;
VAL_ 2332487331 M2P_BUS5_HVState_19 0 "Bus Power off" 1 "Bus Power on" ;
VAL_ 2332487331 M2P_BUS6_HVState_19 0 "Bus Power off" 1 "Bus Power on" ;
VAL_ 2332487331 M2P_BUS7_HVState_19 0 "Bus Power off" 1 "Bus Power on" ;
VAL_ 2332487331 M2P_BUS8_HVState_19 0 "Bus Power off" 1 "Bus Power on" ;
VAL_ 2332487331 M2P_BUS9_HVState_19 0 "Bus Power off" 1 "Bus Power on" ;
VAL_ 2332487331 M2P_BUS10_HVState_19 0 "Bus Power off" 1 "Bus Power on" ;
VAL_ 2332487331 M2P_BUS11_HVState_19 0 "Bus Power off" 1 "Bus Power on" ;
VAL_ 2332487331 M2P_BUS12_HVState_19 0 "Bus Power off" 1 "Bus Power on" ;
VAL_ 2332487332 M2P_StepChrMode_20 0 "Disable" 1 "Enable" 2 "Invalid" 3 "Default" ;
VAL_ 2332487332 M2P_BUS1_HVState_20 0 "Bus Power off" 1 "Bus Power on" ;
VAL_ 2332487332 M2P_BUS2_HVState_20 0 "Bus Power off" 1 "Bus Power on" ;
VAL_ 2332487332 M2P_BUS3_HVState_20 0 "Bus Power off" 1 "Bus Power on" ;
VAL_ 2332487332 M2P_BUS4_HVState_20 0 "Bus Power off" 1 "Bus Power on" ;
VAL_ 2332487332 M2P_BUS5_HVState_20 0 "Bus Power off" 1 "Bus Power on" ;
VAL_ 2332487332 M2P_BUS6_HVState_20 0 "Bus Power off" 1 "Bus Power on" ;
VAL_ 2332487332 M2P_BUS7_HVState_20 0 "Bus Power off" 1 "Bus Power on" ;
VAL_ 2332487332 M2P_BUS8_HVState_20 0 "Bus Power off" 1 "Bus Power on" ;
VAL_ 2332487332 M2P_BUS9_HVState_20 0 "Bus Power off" 1 "Bus Power on" ;
VAL_ 2332487332 M2P_BUS10_HVState_20 0 "Bus Power off" 1 "Bus Power on" ;
VAL_ 2332487332 M2P_BUS11_HVState_20 0 "Bus Power off" 1 "Bus Power on" ;
VAL_ 2332487332 M2P_BUS12_HVState_20 0 "Bus Power off" 1 "Bus Power on" ;
VAL_ 2332487333 M2P_StepChrMode_21 0 "Disable" 1 "Enable" 2 "Invalid" 3 "Default" ;
VAL_ 2332487333 M2P_BUS1_HVState_21 0 "Bus Power off" 1 "Bus Power on" ;
VAL_ 2332487333 M2P_BUS2_HVState_21 0 "Bus Power off" 1 "Bus Power on" ;
VAL_ 2332487333 M2P_BUS3_HVState_21 0 "Bus Power off" 1 "Bus Power on" ;
VAL_ 2332487333 M2P_BUS4_HVState_21 0 "Bus Power off" 1 "Bus Power on" ;
VAL_ 2332487333 M2P_BUS5_HVState_21 0 "Bus Power off" 1 "Bus Power on" ;
VAL_ 2332487333 M2P_BUS6_HVState_21 0 "Bus Power off" 1 "Bus Power on" ;
VAL_ 2332487333 M2P_BUS7_HVState_21 0 "Bus Power off" 1 "Bus Power on" ;
VAL_ 2332487333 M2P_BUS8_HVState_21 0 "Bus Power off" 1 "Bus Power on" ;
VAL_ 2332487333 M2P_BUS9_HVState_21 0 "Bus Power off" 1 "Bus Power on" ;
VAL_ 2332487333 M2P_BUS10_HVState_21 0 "Bus Power off" 1 "Bus Power on" ;
VAL_ 2332487333 M2P_BUS11_HVState_21 0 "Bus Power off" 1 "Bus Power on" ;
VAL_ 2332487333 M2P_BUS12_HVState_21 0 "Bus Power off" 1 "Bus Power on" ;
VAL_ 2332487334 M2P_StepChrMode_22 0 "Disable" 1 "Enable" 2 "Invalid" 3 "Default" ;
VAL_ 2332487334 M2P_BUS1_HVState_22 0 "Bus Power off" 1 "Bus Power on" ;
VAL_ 2332487334 M2P_BUS2_HVState_22 0 "Bus Power off" 1 "Bus Power on" ;
VAL_ 2332487334 M2P_BUS3_HVState_22 0 "Bus Power off" 1 "Bus Power on" ;
VAL_ 2332487334 M2P_BUS4_HVState_22 0 "Bus Power off" 1 "Bus Power on" ;
VAL_ 2332487334 M2P_BUS5_HVState_22 0 "Bus Power off" 1 "Bus Power on" ;
VAL_ 2332487334 M2P_BUS6_HVState_22 0 "Bus Power off" 1 "Bus Power on" ;
VAL_ 2332487334 M2P_BUS7_HVState_22 0 "Bus Power off" 1 "Bus Power on" ;
VAL_ 2332487334 M2P_BUS8_HVState_22 0 "Bus Power off" 1 "Bus Power on" ;
VAL_ 2332487334 M2P_BUS9_HVState_22 0 "Bus Power off" 1 "Bus Power on" ;
VAL_ 2332487334 M2P_BUS10_HVState_22 0 "Bus Power off" 1 "Bus Power on" ;
VAL_ 2332487334 M2P_BUS11_HVState_22 0 "Bus Power off" 1 "Bus Power on" ;
VAL_ 2332487334 M2P_BUS12_HVState_22 0 "Bus Power off" 1 "Bus Power on" ;
VAL_ 2332487335 M2P_StepChrMode_23 0 "Disable" 1 "Enable" 2 "Invalid" 3 "Default" ;
VAL_ 2332487335 M2P_BUS1_HVState_23 0 "Bus Power off" 1 "Bus Power on" ;
VAL_ 2332487335 M2P_BUS2_HVState_23 0 "Bus Power off" 1 "Bus Power on" ;
VAL_ 2332487335 M2P_BUS3_HVState_23 0 "Bus Power off" 1 "Bus Power on" ;
VAL_ 2332487335 M2P_BUS4_HVState_23 0 "Bus Power off" 1 "Bus Power on" ;
VAL_ 2332487335 M2P_BUS5_HVState_23 0 "Bus Power off" 1 "Bus Power on" ;
VAL_ 2332487335 M2P_BUS6_HVState_23 0 "Bus Power off" 1 "Bus Power on" ;
VAL_ 2332487335 M2P_BUS7_HVState_23 0 "Bus Power off" 1 "Bus Power on" ;
VAL_ 2332487335 M2P_BUS8_HVState_23 0 "Bus Power off" 1 "Bus Power on" ;
VAL_ 2332487335 M2P_BUS9_HVState_23 0 "Bus Power off" 1 "Bus Power on" ;
VAL_ 2332487335 M2P_BUS10_HVState_23 0 "Bus Power off" 1 "Bus Power on" ;
VAL_ 2332487335 M2P_BUS11_HVState_23 0 "Bus Power off" 1 "Bus Power on" ;
VAL_ 2332487335 M2P_BUS12_HVState_23 0 "Bus Power off" 1 "Bus Power on" ;
VAL_ 2332487336 M2P_StepChrMode_24 0 "Disable" 1 "Enable" 2 "Invalid" 3 "Default" ;
VAL_ 2332487336 M2P_BUS1_HVState_24 0 "Bus Power off" 1 "Bus Power on" ;
VAL_ 2332487336 M2P_BUS2_HVState_24 0 "Bus Power off" 1 "Bus Power on" ;
VAL_ 2332487336 M2P_BUS3_HVState_24 0 "Bus Power off" 1 "Bus Power on" ;
VAL_ 2332487336 M2P_BUS4_HVState_24 0 "Bus Power off" 1 "Bus Power on" ;
VAL_ 2332487336 M2P_BUS5_HVState_24 0 "Bus Power off" 1 "Bus Power on" ;
VAL_ 2332487336 M2P_BUS6_HVState_24 0 "Bus Power off" 1 "Bus Power on" ;
VAL_ 2332487336 M2P_BUS7_HVState_24 0 "Bus Power off" 1 "Bus Power on" ;
VAL_ 2332487336 M2P_BUS8_HVState_24 0 "Bus Power off" 1 "Bus Power on" ;
VAL_ 2332487336 M2P_BUS9_HVState_24 0 "Bus Power off" 1 "Bus Power on" ;
VAL_ 2332487336 M2P_BUS10_HVState_24 0 "Bus Power off" 1 "Bus Power on" ;
VAL_ 2332487336 M2P_BUS11_HVState_24 0 "Bus Power off" 1 "Bus Power on" ;
VAL_ 2332487336 M2P_BUS12_HVState_24 0 "Bus Power off" 1 "Bus Power on" ;
VAL_ 2332487337 M2P_StepChrMode_25 0 "Disable" 1 "Enable" 2 "Invalid" 3 "Default" ;
VAL_ 2332487337 M2P_BUS1_HVState_25 0 "Bus Power off" 1 "Bus Power on" ;
VAL_ 2332487337 M2P_BUS2_HVState_25 0 "Bus Power off" 1 "Bus Power on" ;
VAL_ 2332487337 M2P_BUS3_HVState_25 0 "Bus Power off" 1 "Bus Power on" ;
VAL_ 2332487337 M2P_BUS4_HVState_25 0 "Bus Power off" 1 "Bus Power on" ;
VAL_ 2332487337 M2P_BUS5_HVState_25 0 "Bus Power off" 1 "Bus Power on" ;
VAL_ 2332487337 M2P_BUS6_HVState_25 0 "Bus Power off" 1 "Bus Power on" ;
VAL_ 2332487337 M2P_BUS7_HVState_25 0 "Bus Power off" 1 "Bus Power on" ;
VAL_ 2332487337 M2P_BUS8_HVState_25 0 "Bus Power off" 1 "Bus Power on" ;
VAL_ 2332487337 M2P_BUS9_HVState_25 0 "Bus Power off" 1 "Bus Power on" ;
VAL_ 2332487337 M2P_BUS10_HVState_25 0 "Bus Power off" 1 "Bus Power on" ;
VAL_ 2332487337 M2P_BUS11_HVState_25 0 "Bus Power off" 1 "Bus Power on" ;
VAL_ 2332487337 M2P_BUS12_HVState_25 0 "Bus Power off" 1 "Bus Power on" ;
VAL_ 2332487338 M2P_StepChrMode_26 0 "Disable" 1 "Enable" 2 "Invalid" 3 "Default" ;
VAL_ 2332487338 M2P_BUS1_HVState_26 0 "Bus Power off" 1 "Bus Power on" ;
VAL_ 2332487338 M2P_BUS2_HVState_26 0 "Bus Power off" 1 "Bus Power on" ;
VAL_ 2332487338 M2P_BUS3_HVState_26 0 "Bus Power off" 1 "Bus Power on" ;
VAL_ 2332487338 M2P_BUS4_HVState_26 0 "Bus Power off" 1 "Bus Power on" ;
VAL_ 2332487338 M2P_BUS5_HVState_26 0 "Bus Power off" 1 "Bus Power on" ;
VAL_ 2332487338 M2P_BUS6_HVState_26 0 "Bus Power off" 1 "Bus Power on" ;
VAL_ 2332487338 M2P_BUS7_HVState_26 0 "Bus Power off" 1 "Bus Power on" ;
VAL_ 2332487338 M2P_BUS8_HVState_26 0 "Bus Power off" 1 "Bus Power on" ;
VAL_ 2332487338 M2P_BUS9_HVState_26 0 "Bus Power off" 1 "Bus Power on" ;
VAL_ 2332487338 M2P_BUS10_HVState_26 0 "Bus Power off" 1 "Bus Power on" ;
VAL_ 2332487338 M2P_BUS11_HVState_26 0 "Bus Power off" 1 "Bus Power on" ;
VAL_ 2332487338 M2P_BUS12_HVState_26 0 "Bus Power off" 1 "Bus Power on" ;
VAL_ 2332487339 M2P_StepChrMode_27 0 "Disable" 1 "Enable" 2 "Invalid" 3 "Default" ;
VAL_ 2332487339 M2P_BUS1_HVState_27 0 "Bus Power off" 1 "Bus Power on" ;
VAL_ 2332487339 M2P_BUS2_HVState_27 0 "Bus Power off" 1 "Bus Power on" ;
VAL_ 2332487339 M2P_BUS3_HVState_27 0 "Bus Power off" 1 "Bus Power on" ;
VAL_ 2332487339 M2P_BUS4_HVState_27 0 "Bus Power off" 1 "Bus Power on" ;
VAL_ 2332487339 M2P_BUS5_HVState_27 0 "Bus Power off" 1 "Bus Power on" ;
VAL_ 2332487339 M2P_BUS6_HVState_27 0 "Bus Power off" 1 "Bus Power on" ;
VAL_ 2332487339 M2P_BUS7_HVState_27 0 "Bus Power off" 1 "Bus Power on" ;
VAL_ 2332487339 M2P_BUS8_HVState_27 0 "Bus Power off" 1 "Bus Power on" ;
VAL_ 2332487339 M2P_BUS9_HVState_27 0 "Bus Power off" 1 "Bus Power on" ;
VAL_ 2332487339 M2P_BUS10_HVState_27 0 "Bus Power off" 1 "Bus Power on" ;
VAL_ 2332487339 M2P_BUS11_HVState_27 0 "Bus Power off" 1 "Bus Power on" ;
VAL_ 2332487339 M2P_BUS12_HVState_27 0 "Bus Power off" 1 "Bus Power on" ;
VAL_ 2332487340 M2P_StepChrMode_28 0 "Disable" 1 "Enable" 2 "Invalid" 3 "Default" ;
VAL_ 2332487340 M2P_BUS1_HVState_28 0 "Bus Power off" 1 "Bus Power on" ;
VAL_ 2332487340 M2P_BUS2_HVState_28 0 "Bus Power off" 1 "Bus Power on" ;
VAL_ 2332487340 M2P_BUS3_HVState_28 0 "Bus Power off" 1 "Bus Power on" ;
VAL_ 2332487340 M2P_BUS4_HVState_28 0 "Bus Power off" 1 "Bus Power on" ;
VAL_ 2332487340 M2P_BUS5_HVState_28 0 "Bus Power off" 1 "Bus Power on" ;
VAL_ 2332487340 M2P_BUS6_HVState_28 0 "Bus Power off" 1 "Bus Power on" ;
VAL_ 2332487340 M2P_BUS7_HVState_28 0 "Bus Power off" 1 "Bus Power on" ;
VAL_ 2332487340 M2P_BUS8_HVState_28 0 "Bus Power off" 1 "Bus Power on" ;
VAL_ 2332487340 M2P_BUS9_HVState_28 0 "Bus Power off" 1 "Bus Power on" ;
VAL_ 2332487340 M2P_BUS10_HVState_28 0 "Bus Power off" 1 "Bus Power on" ;
VAL_ 2332487340 M2P_BUS11_HVState_28 0 "Bus Power off" 1 "Bus Power on" ;
VAL_ 2332487340 M2P_BUS12_HVState_28 0 "Bus Power off" 1 "Bus Power on" ;
VAL_ 2332487341 M2P_StepChrMode_29 0 "Disable" 1 "Enable" 2 "Invalid" 3 "Default" ;
VAL_ 2332487341 M2P_BUS1_HVState_29 0 "Bus Power off" 1 "Bus Power on" ;
VAL_ 2332487341 M2P_BUS2_HVState_29 0 "Bus Power off" 1 "Bus Power on" ;
VAL_ 2332487341 M2P_BUS3_HVState_29 0 "Bus Power off" 1 "Bus Power on" ;
VAL_ 2332487341 M2P_BUS4_HVState_29 0 "Bus Power off" 1 "Bus Power on" ;
VAL_ 2332487341 M2P_BUS5_HVState_29 0 "Bus Power off" 1 "Bus Power on" ;
VAL_ 2332487341 M2P_BUS6_HVState_29 0 "Bus Power off" 1 "Bus Power on" ;
VAL_ 2332487341 M2P_BUS7_HVState_29 0 "Bus Power off" 1 "Bus Power on" ;
VAL_ 2332487341 M2P_BUS8_HVState_29 0 "Bus Power off" 1 "Bus Power on" ;
VAL_ 2332487341 M2P_BUS9_HVState_29 0 "Bus Power off" 1 "Bus Power on" ;
VAL_ 2332487341 M2P_BUS10_HVState_29 0 "Bus Power off" 1 "Bus Power on" ;
VAL_ 2332487341 M2P_BUS11_HVState_29 0 "Bus Power off" 1 "Bus Power on" ;
VAL_ 2332487341 M2P_BUS12_HVState_29 0 "Bus Power off" 1 "Bus Power on" ;
VAL_ 2332487342 M2P_StepChrMode_30 0 "Disable" 1 "Enable" 2 "Invalid" 3 "Default" ;
VAL_ 2332487342 M2P_BUS1_HVState_30 0 "Bus Power off" 1 "Bus Power on" ;
VAL_ 2332487342 M2P_BUS2_HVState_30 0 "Bus Power off" 1 "Bus Power on" ;
VAL_ 2332487342 M2P_BUS3_HVState_30 0 "Bus Power off" 1 "Bus Power on" ;
VAL_ 2332487342 M2P_BUS4_HVState_30 0 "Bus Power off" 1 "Bus Power on" ;
VAL_ 2332487342 M2P_BUS5_HVState_30 0 "Bus Power off" 1 "Bus Power on" ;
VAL_ 2332487342 M2P_BUS6_HVState_30 0 "Bus Power off" 1 "Bus Power on" ;
VAL_ 2332487342 M2P_BUS7_HVState_30 0 "Bus Power off" 1 "Bus Power on" ;
VAL_ 2332487342 M2P_BUS8_HVState_30 0 "Bus Power off" 1 "Bus Power on" ;
VAL_ 2332487342 M2P_BUS9_HVState_30 0 "Bus Power off" 1 "Bus Power on" ;
VAL_ 2332487342 M2P_BUS10_HVState_30 0 "Bus Power off" 1 "Bus Power on" ;
VAL_ 2332487342 M2P_BUS11_HVState_30 0 "Bus Power off" 1 "Bus Power on" ;
VAL_ 2332487342 M2P_BUS12_HVState_30 0 "Bus Power off" 1 "Bus Power on" ;
VAL_ 2332487343 M2P_StepChrMode_31 0 "Disable" 1 "Enable" 2 "Invalid" 3 "Default" ;
VAL_ 2332487343 M2P_BUS1_HVState_31 0 "Bus Power off" 1 "Bus Power on" ;
VAL_ 2332487343 M2P_BUS2_HVState_31 0 "Bus Power off" 1 "Bus Power on" ;
VAL_ 2332487343 M2P_BUS3_HVState_31 0 "Bus Power off" 1 "Bus Power on" ;
VAL_ 2332487343 M2P_BUS4_HVState_31 0 "Bus Power off" 1 "Bus Power on" ;
VAL_ 2332487343 M2P_BUS5_HVState_31 0 "Bus Power off" 1 "Bus Power on" ;
VAL_ 2332487343 M2P_BUS6_HVState_31 0 "Bus Power off" 1 "Bus Power on" ;
VAL_ 2332487343 M2P_BUS7_HVState_31 0 "Bus Power off" 1 "Bus Power on" ;
VAL_ 2332487343 M2P_BUS8_HVState_31 0 "Bus Power off" 1 "Bus Power on" ;
VAL_ 2332487343 M2P_BUS9_HVState_31 0 "Bus Power off" 1 "Bus Power on" ;
VAL_ 2332487343 M2P_BUS10_HVState_31 0 "Bus Power off" 1 "Bus Power on" ;
VAL_ 2332487343 M2P_BUS11_HVState_31 0 "Bus Power off" 1 "Bus Power on" ;
VAL_ 2332487343 M2P_BUS12_HVState_31 0 "Bus Power off" 1 "Bus Power on" ;
VAL_ 2332552849 M2P_SysremainEngy_Charge_01 65535 "Invalid" ;
VAL_ 2332552849 M2P_SysremainEngy_DisCharge_01 65535 "Invalid" ;
VAL_ 2332552849 M2P_SOE_Charge_01 1023 "Invalid" ;
VAL_ 2332552849 M2P_SOE_Discharge_01 1023 "Invalid" ;
VAL_ 2332552850 M2P_SysremainEngy_Charge_02 65535 "Invalid" ;
VAL_ 2332552850 M2P_SysremainEngy_DisCharge_02 65535 "Invalid" ;
VAL_ 2332552850 M2P_SOE_Charge_02 1023 "Invalid" ;
VAL_ 2332552850 M2P_SOE_Discharge_02 1023 "Invalid" ;
VAL_ 2332552851 M2P_SysremainEngy_Charge_03 65535 "Invalid" ;
VAL_ 2332552851 M2P_SysremainEngy_DisCharge_03 65535 "Invalid" ;
VAL_ 2332552851 M2P_SOE_Charge_03 1023 "Invalid" ;
VAL_ 2332552851 M2P_SOE_Discharge_03 1023 "Invalid" ;
VAL_ 2332552852 M2P_SysremainEngy_Charge_04 65535 "Invalid" ;
VAL_ 2332552852 M2P_SysremainEngy_DisCharge_04 65535 "Invalid" ;
VAL_ 2332552852 M2P_SOE_Charge_04 1023 "Invalid" ;
VAL_ 2332552852 M2P_SOE_Discharge_04 1023 "Invalid" ;
VAL_ 2332552853 M2P_SysremainEngy_Charge_05 65535 "Invalid" ;
VAL_ 2332552853 M2P_SysremainEngy_DisCharge_05 65535 "Invalid" ;
VAL_ 2332552853 M2P_SOE_Charge_05 1023 "Invalid" ;
VAL_ 2332552853 M2P_SOE_Discharge_05 1023 "Invalid" ;
VAL_ 2332552854 M2P_SysremainEngy_Charge_06 65535 "Invalid" ;
VAL_ 2332552854 M2P_SysremainEngy_DisCharge_06 65535 "Invalid" ;
VAL_ 2332552854 M2P_SOE_Charge_06 1023 "Invalid" ;
VAL_ 2332552854 M2P_SOE_Discharge_06 1023 "Invalid" ;
VAL_ 2332552855 M2P_SysremainEngy_Charge_07 65535 "Invalid" ;
VAL_ 2332552855 M2P_SysremainEngy_DisCharge_07 65535 "Invalid" ;
VAL_ 2332552855 M2P_SOE_Charge_07 1023 "Invalid" ;
VAL_ 2332552855 M2P_SOE_Discharge_07 1023 "Invalid" ;
VAL_ 2332552856 M2P_SysremainEngy_Charge_08 65535 "Invalid" ;
VAL_ 2332552856 M2P_SysremainEngy_DisCharge_08 65535 "Invalid" ;
VAL_ 2332552856 M2P_SOE_Charge_08 1023 "Invalid" ;
VAL_ 2332552856 M2P_SOE_Discharge_08 1023 "Invalid" ;
VAL_ 2332552857 M2P_SysremainEngy_Charge_09 65535 "Invalid" ;
VAL_ 2332552857 M2P_SysremainEngy_DisCharge_09 65535 "Invalid" ;
VAL_ 2332552857 M2P_SOE_Charge_09 1023 "Invalid" ;
VAL_ 2332552857 M2P_SOE_Discharge_09 1023 "Invalid" ;
VAL_ 2332552858 M2P_SysremainEngy_Charge_10 65535 "Invalid" ;
VAL_ 2332552858 M2P_SysremainEngy_DisCharge_10 65535 "Invalid" ;
VAL_ 2332552858 M2P_SOE_Charge_10 1023 "Invalid" ;
VAL_ 2332552858 M2P_SOE_Discharge_10 1023 "Invalid" ;
VAL_ 2332552859 M2P_SysremainEngy_Charge_11 65535 "Invalid" ;
VAL_ 2332552859 M2P_SysremainEngy_DisCharge_11 65535 "Invalid" ;
VAL_ 2332552859 M2P_SOE_Charge_11 1023 "Invalid" ;
VAL_ 2332552859 M2P_SOE_Discharge_11 1023 "Invalid" ;
VAL_ 2332552860 M2P_SysremainEngy_Charge_12 65535 "Invalid" ;
VAL_ 2332552860 M2P_SysremainEngy_DisCharge_12 65535 "Invalid" ;
VAL_ 2332552860 M2P_SOE_Charge_12 1023 "Invalid" ;
VAL_ 2332552860 M2P_SOE_Discharge_12 1023 "Invalid" ;
VAL_ 2332552861 M2P_SysremainEngy_Charge_13 65535 "Invalid" ;
VAL_ 2332552861 M2P_SysremainEngy_DisCharge_13 65535 "Invalid" ;
VAL_ 2332552861 M2P_SOE_Charge_13 1023 "Invalid" ;
VAL_ 2332552861 M2P_SOE_Discharge_13 1023 "Invalid" ;
VAL_ 2332552862 M2P_SysremainEngy_Charge_14 65535 "Invalid" ;
VAL_ 2332552862 M2P_SysremainEngy_DisCharge_14 65535 "Invalid" ;
VAL_ 2332552862 M2P_SOE_Charge_14 1023 "Invalid" ;
VAL_ 2332552862 M2P_SOE_Discharge_14 1023 "Invalid" ;
VAL_ 2332552863 M2P_SysremainEngy_Charge_15 65535 "Invalid" ;
VAL_ 2332552863 M2P_SysremainEngy_DisCharge_15 65535 "Invalid" ;
VAL_ 2332552863 M2P_SOE_Charge_15 1023 "Invalid" ;
VAL_ 2332552863 M2P_SOE_Discharge_15 1023 "Invalid" ;
VAL_ 2332552864 M2P_SysremainEngy_Charge_16 65535 "Invalid" ;
VAL_ 2332552864 M2P_SysremainEngy_DisCharge_16 65535 "Invalid" ;
VAL_ 2332552864 M2P_SOE_Charge_16 1023 "Invalid" ;
VAL_ 2332552864 M2P_SOE_Discharge_16 1023 "Invalid" ;
VAL_ 2332552865 M2P_SysremainEngy_Charge_17 65535 "Invalid" ;
VAL_ 2332552865 M2P_SysremainEngy_DisCharge_17 65535 "Invalid" ;
VAL_ 2332552865 M2P_SOE_Charge_17 1023 "Invalid" ;
VAL_ 2332552865 M2P_SOE_Discharge_17 1023 "Invalid" ;
VAL_ 2332552866 M2P_SysremainEngy_Charge_18 65535 "Invalid" ;
VAL_ 2332552866 M2P_SysremainEngy_DisCharge_18 65535 "Invalid" ;
VAL_ 2332552866 M2P_SOE_Charge_18 1023 "Invalid" ;
VAL_ 2332552866 M2P_SOE_Discharge_18 1023 "Invalid" ;
VAL_ 2332552867 M2P_SysremainEngy_Charge_19 65535 "Invalid" ;
VAL_ 2332552867 M2P_SysremainEngy_DisCharge_19 65535 "Invalid" ;
VAL_ 2332552867 M2P_SOE_Charge_19 1023 "Invalid" ;
VAL_ 2332552867 M2P_SOE_Discharge_19 1023 "Invalid" ;
VAL_ 2332552868 M2P_SysremainEngy_Charge_20 65535 "Invalid" ;
VAL_ 2332552868 M2P_SysremainEngy_DisCharge_20 65535 "Invalid" ;
VAL_ 2332552868 M2P_SOE_Charge_20 1023 "Invalid" ;
VAL_ 2332552868 M2P_SOE_Discharge_20 1023 "Invalid" ;
VAL_ 2332552869 M2P_SysremainEngy_Charge_21 65535 "Invalid" ;
VAL_ 2332552869 M2P_SysremainEngy_DisCharge_21 65535 "Invalid" ;
VAL_ 2332552869 M2P_SOE_Charge_21 1023 "Invalid" ;
VAL_ 2332552869 M2P_SOE_Discharge_21 1023 "Invalid" ;
VAL_ 2332552870 M2P_SysremainEngy_Charge_22 65535 "Invalid" ;
VAL_ 2332552870 M2P_SysremainEngy_DisCharge_22 65535 "Invalid" ;
VAL_ 2332552870 M2P_SOE_Charge_22 1023 "Invalid" ;
VAL_ 2332552870 M2P_SOE_Discharge_22 1023 "Invalid" ;
VAL_ 2332552871 M2P_SysremainEngy_Charge_23 65535 "Invalid" ;
VAL_ 2332552871 M2P_SysremainEngy_DisCharge_23 65535 "Invalid" ;
VAL_ 2332552871 M2P_SOE_Charge_23 1023 "Invalid" ;
VAL_ 2332552871 M2P_SOE_Discharge_23 1023 "Invalid" ;
VAL_ 2332552872 M2P_SysremainEngy_Charge_24 65535 "Invalid" ;
VAL_ 2332552872 M2P_SysremainEngy_DisCharge_24 65535 "Invalid" ;
VAL_ 2332552872 M2P_SOE_Charge_24 1023 "Invalid" ;
VAL_ 2332552872 M2P_SOE_Discharge_24 1023 "Invalid" ;
VAL_ 2332552873 M2P_SysremainEngy_Charge_25 65535 "Invalid" ;
VAL_ 2332552873 M2P_SysremainEngy_DisCharge_25 65535 "Invalid" ;
VAL_ 2332552873 M2P_SOE_Charge_25 1023 "Invalid" ;
VAL_ 2332552873 M2P_SOE_Discharge_25 1023 "Invalid" ;
VAL_ 2332552874 M2P_SysremainEngy_Charge_26 65535 "Invalid" ;
VAL_ 2332552874 M2P_SysremainEngy_DisCharge_26 65535 "Invalid" ;
VAL_ 2332552874 M2P_SOE_Charge_26 1023 "Invalid" ;
VAL_ 2332552874 M2P_SOE_Discharge_26 1023 "Invalid" ;
VERSION ""

NS_ :

BS_:

BU_: MBMU PC SBMU IMM ETH DCDC LEMS

BO_ 2332552875 M2P_SUMDATA7__27: 8 MBMU
 SG_ M2P_SysremainEngy_Charge_27 : 0|16@1+ (1,0) [0|65535] "Kwh"  PC
 SG_ M2P_SysremainEngy_DisCharge_27 : 16|16@1+ (1,0) [0|65535] "Kwh"  PC
 SG_ M2P_SOE_Charge_27 : 32|10@1+ (0.1,0) [0|102.3] "%"  PC
 SG_ M2P_SOE_Discharge_27 : 42|10@1+ (0.1,0) [0|102.3] "%"  PC

BO_ 2332552876 M2P_SUMDATA7__28: 8 MBMU
 SG_ M2P_SysremainEngy_Charge_28 : 0|16@1+ (1,0) [0|65535] "Kwh"  PC
 SG_ M2P_SysremainEngy_DisCharge_28 : 16|16@1+ (1,0) [0|65535] "Kwh"  PC
 SG_ M2P_SOE_Charge_28 : 32|10@1+ (0.1,0) [0|102.3] "%"  PC
 SG_ M2P_SOE_Discharge_28 : 42|10@1+ (0.1,0) [0|102.3] "%"  PC

BO_ 2332552877 M2P_SUMDATA7__29: 8 MBMU
 SG_ M2P_SysremainEngy_Charge_29 : 0|16@1+ (1,0) [0|65535] "Kwh"  PC
 SG_ M2P_SysremainEngy_DisCharge_29 : 16|16@1+ (1,0) [0|65535] "Kwh"  PC
 SG_ M2P_SOE_Charge_29 : 32|10@1+ (0.1,0) [0|102.3] "%"  PC
 SG_ M2P_SOE_Discharge_29 : 42|10@1+ (0.1,0) [0|102.3] "%"  PC

BO_ 2332552878 M2P_SUMDATA7__30: 8 MBMU
 SG_ M2P_SysremainEngy_Charge_30 : 0|16@1+ (1,0) [0|65535] "Kwh"  PC
 SG_ M2P_SysremainEngy_DisCharge_30 : 16|16@1+ (1,0) [0|65535] "Kwh"  PC
 SG_ M2P_SOE_Charge_30 : 32|10@1+ (0.1,0) [0|102.3] "%"  PC
 SG_ M2P_SOE_Discharge_30 : 42|10@1+ (0.1,0) [0|102.3] "%"  PC

BO_ 2332552879 M2P_SUMDATA7__31: 8 MBMU
 SG_ M2P_SysremainEngy_Charge_31 : 0|16@1+ (1,0) [0|65535] "Kwh"  PC
 SG_ M2P_SysremainEngy_DisCharge_31 : 16|16@1+ (1,0) [0|65535] "Kwh"  PC
 SG_ M2P_SOE_Charge_31 : 32|10@1+ (0.1,0) [0|102.3] "%"  PC
 SG_ M2P_SOE_Discharge_31 : 42|10@1+ (0.1,0) [0|102.3] "%"  PC

BO_ 2400382609 M2P_PCSInfo__01: 8 MBMU
 SG_ M2P_HisChgCap : 0|32@1+ (1,0) [0|65535] ""  PC
 SG_ M2P_HisDchgCap : 32|32@1+ (1,0) [0|65535] ""  PC

BO_ 2400382610 M2P_PCSInfo__02: 8 MBMU
 SG_ M2P_HisChgCap : 0|32@1+ (1,0) [0|65535] ""  PC
 SG_ M2P_HisDchgCap : 32|32@1+ (1,0) [0|65535] ""  PC

BO_ 2400382611 M2P_PCSInfo__03: 8 MBMU
 SG_ M2P_HisChgCap : 0|32@1+ (1,0) [0|65535] ""  PC
 SG_ M2P_HisDchgCap : 32|32@1+ (1,0) [0|65535] ""  PC

BO_ 2400382612 M2P_PCSInfo__04: 8 MBMU
 SG_ M2P_HisChgCap : 0|32@1+ (1,0) [0|65535] ""  PC
 SG_ M2P_HisDchgCap : 32|32@1+ (1,0) [0|65535] ""  PC

BO_ 2400382613 M2P_PCSInfo__05: 8 MBMU
 SG_ M2P_HisChgCap : 0|32@1+ (1,0) [0|65535] ""  PC
 SG_ M2P_HisDchgCap : 32|32@1+ (1,0) [0|65535] ""  PC

BO_ 2400382614 M2P_PCSInfo__06: 8 MBMU
 SG_ M2P_HisChgCap : 0|32@1+ (1,0) [0|65535] ""  PC
 SG_ M2P_HisDchgCap : 32|32@1+ (1,0) [0|65535] ""  PC

BO_ 2400382615 M2P_PCSInfo__07: 8 MBMU
 SG_ M2P_HisChgCap : 0|32@1+ (1,0) [0|65535] ""  PC
 SG_ M2P_HisDchgCap : 32|32@1+ (1,0) [0|65535] ""  PC

BO_ 2400382616 M2P_PCSInfo__08: 8 MBMU
 SG_ M2P_HisChgCap : 0|32@1+ (1,0) [0|65535] ""  PC
 SG_ M2P_HisDchgCap : 32|32@1+ (1,0) [0|65535] ""  PC

BO_ 2400382617 M2P_PCSInfo__09: 8 MBMU
 SG_ M2P_HisChgCap : 0|32@1+ (1,0) [0|65535] ""  PC
 SG_ M2P_HisDchgCap : 32|32@1+ (1,0) [0|65535] ""  PC

BO_ 2400382618 M2P_PCSInfo__10: 8 MBMU
 SG_ M2P_HisChgCap : 0|32@1+ (1,0) [0|65535] ""  PC
 SG_ M2P_HisDchgCap : 32|32@1+ (1,0) [0|65535] ""  PC

BO_ 2400382619 M2P_PCSInfo__11: 8 MBMU
 SG_ M2P_HisChgCap : 0|32@1+ (1,0) [0|65535] ""  PC
 SG_ M2P_HisDchgCap : 32|32@1+ (1,0) [0|65535] ""  PC

BO_ 2400382620 M2P_PCSInfo__12: 8 MBMU
 SG_ M2P_HisChgCap : 0|32@1+ (1,0) [0|65535] ""  PC
 SG_ M2P_HisDchgCap : 32|32@1+ (1,0) [0|65535] ""  PC

BO_ 2400382621 M2P_PCSInfo__13: 8 MBMU
 SG_ M2P_HisChgCap : 0|32@1+ (1,0) [0|65535] ""  PC
 SG_ M2P_HisDchgCap : 32|32@1+ (1,0) [0|65535] ""  PC

BO_ 2400382622 M2P_PCSInfo__14: 8 MBMU
 SG_ M2P_HisChgCap : 0|32@1+ (1,0) [0|65535] ""  PC
 SG_ M2P_HisDchgCap : 32|32@1+ (1,0) [0|65535] ""  PC

BO_ 2400382623 M2P_PCSInfo__15: 8 MBMU
 SG_ M2P_HisChgCap : 0|32@1+ (1,0) [0|65535] ""  PC
 SG_ M2P_HisDchgCap : 32|32@1+ (1,0) [0|65535] ""  PC

BO_ 2400382624 M2P_PCSInfo__16: 8 MBMU
 SG_ M2P_HisChgCap : 0|32@1+ (1,0) [0|65535] ""  PC
 SG_ M2P_HisDchgCap : 32|32@1+ (1,0) [0|65535] ""  PC

BO_ 2400382625 M2P_PCSInfo__17: 8 MBMU
 SG_ M2P_HisChgCap : 0|32@1+ (1,0) [0|65535] ""  PC
 SG_ M2P_HisDchgCap : 32|32@1+ (1,0) [0|65535] ""  PC

BO_ 2400382626 M2P_PCSInfo__18: 8 MBMU
 SG_ M2P_HisChgCap : 0|32@1+ (1,0) [0|65535] ""  PC
 SG_ M2P_HisDchgCap : 32|32@1+ (1,0) [0|65535] ""  PC

BO_ 2400382627 M2P_PCSInfo__19: 8 MBMU
 SG_ M2P_HisChgCap : 0|32@1+ (1,0) [0|65535] ""  PC
 SG_ M2P_HisDchgCap : 32|32@1+ (1,0) [0|65535] ""  PC

BO_ 2400382628 M2P_PCSInfo__20: 8 MBMU
 SG_ M2P_HisChgCap : 0|32@1+ (1,0) [0|65535] ""  PC
 SG_ M2P_HisDchgCap : 32|32@1+ (1,0) [0|65535] ""  PC

BO_ 2400382629 M2P_PCSInfo__21: 8 MBMU
 SG_ M2P_HisChgCap : 0|32@1+ (1,0) [0|65535] ""  PC
 SG_ M2P_HisDchgCap : 32|32@1+ (1,0) [0|65535] ""  PC

BO_ 2400382630 M2P_PCSInfo__22: 8 MBMU
 SG_ M2P_HisChgCap : 0|32@1+ (1,0) [0|65535] ""  PC
 SG_ M2P_HisDchgCap : 32|32@1+ (1,0) [0|65535] ""  PC

BO_ 2400382631 M2P_PCSInfo__23: 8 MBMU
 SG_ M2P_HisChgCap : 0|32@1+ (1,0) [0|65535] ""  PC
 SG_ M2P_HisDchgCap : 32|32@1+ (1,0) [0|65535] ""  PC

BO_ 2400382632 M2P_PCSInfo__24: 8 MBMU
 SG_ M2P_HisChgCap : 0|32@1+ (1,0) [0|65535] ""  PC
 SG_ M2P_HisDchgCap : 32|32@1+ (1,0) [0|65535] ""  PC

BO_ 2400382633 M2P_PCSInfo__25: 8 MBMU
 SG_ M2P_HisChgCap : 0|32@1+ (1,0) [0|65535] ""  PC
 SG_ M2P_HisDchgCap : 32|32@1+ (1,0) [0|65535] ""  PC

BO_ 2400382634 M2P_PCSInfo__26: 8 MBMU
 SG_ M2P_HisChgCap : 0|32@1+ (1,0) [0|65535] ""  PC
 SG_ M2P_HisDchgCap : 32|32@1+ (1,0) [0|65535] ""  PC

BO_ 2400382635 M2P_PCSInfo__27: 8 MBMU
 SG_ M2P_HisChgCap : 0|32@1+ (1,0) [0|65535] ""  PC
 SG_ M2P_HisDchgCap : 32|32@1+ (1,0) [0|65535] ""  PC

BO_ 2400382636 M2P_PCSInfo__28: 8 MBMU
 SG_ M2P_HisChgCap : 0|32@1+ (1,0) [0|65535] ""  PC
 SG_ M2P_HisDchgCap : 32|32@1+ (1,0) [0|65535] ""  PC

BO_ 2400382637 M2P_PCSInfo__29: 8 MBMU
 SG_ M2P_HisChgCap : 0|32@1+ (1,0) [0|65535] ""  PC
 SG_ M2P_HisDchgCap : 32|32@1+ (1,0) [0|65535] ""  PC

BO_ 2400382638 M2P_PCSInfo__30: 8 MBMU
 SG_ M2P_HisChgCap : 0|32@1+ (1,0) [0|65535] ""  PC
 SG_ M2P_HisDchgCap : 32|32@1+ (1,0) [0|65535] ""  PC

BO_ 2400382639 M2P_PCSInfo__31: 8 MBMU
 SG_ M2P_HisChgCap : 0|32@1+ (1,0) [0|65535] ""  PC
 SG_ M2P_HisDchgCap : 32|32@1+ (1,0) [0|65535] ""  PC

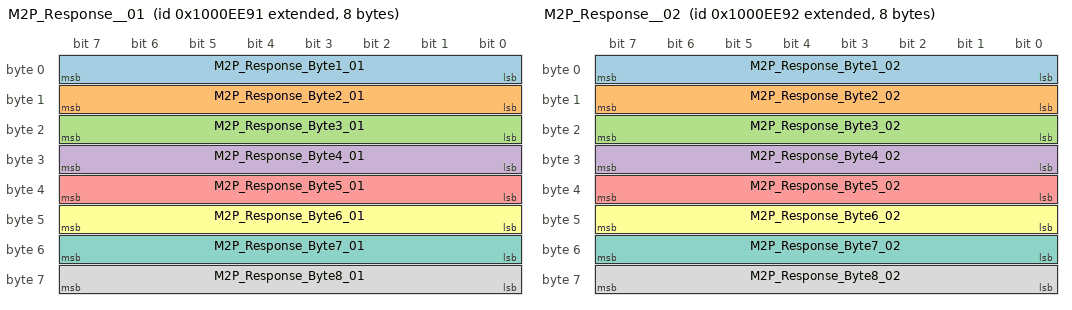
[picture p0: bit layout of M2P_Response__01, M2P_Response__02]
BO_ 2415980177 M2P_Response__01: 8 MBMU
 SG_ M2P_Response_Byte1_01 : 0|8@1+ (1,0) [0|255] ""  PC
 SG_ M2P_Response_Byte2_01 : 8|8@1+ (1,0) [0|255] ""  PC
 SG_ M2P_Response_Byte3_01 : 16|8@1+ (1,0) [0|255] ""  PC
 SG_ M2P_Response_Byte4_01 : 24|8@1+ (1,0) [0|255] ""  PC
 SG_ M2P_Response_Byte5_01 : 32|8@1+ (1,0) [0|255] ""  PC
 SG_ M2P_Response_Byte6_01 : 40|8@1+ (1,0) [0|255] ""  PC
 SG_ M2P_Response_Byte7_01 : 48|8@1+ (1,0) [0|255] ""  PC
 SG_ M2P_Response_Byte8_01 : 56|8@1+ (1,0) [0|255] ""  PC

BO_ 2415980178 M2P_Response__02: 8 MBMU
 SG_ M2P_Response_Byte1_02 : 0|8@1+ (1,0) [0|255] ""  PC
 SG_ M2P_Response_Byte2_02 : 8|8@1+ (1,0) [0|255] ""  PC
 SG_ M2P_Response_Byte3_02 : 16|8@1+ (1,0) [0|255] ""  PC
 SG_ M2P_Response_Byte4_02 : 24|8@1+ (1,0) [0|255] ""  PC
 SG_ M2P_Response_Byte5_02 : 32|8@1+ (1,0) [0|255] ""  PC
 SG_ M2P_Response_Byte6_02 : 40|8@1+ (1,0) [0|255] ""  PC
 SG_ M2P_Response_Byte7_02 : 48|8@1+ (1,0) [0|255] ""  PC
 SG_ M2P_Response_Byte8_02 : 56|8@1+ (1,0) [0|255] ""  PC

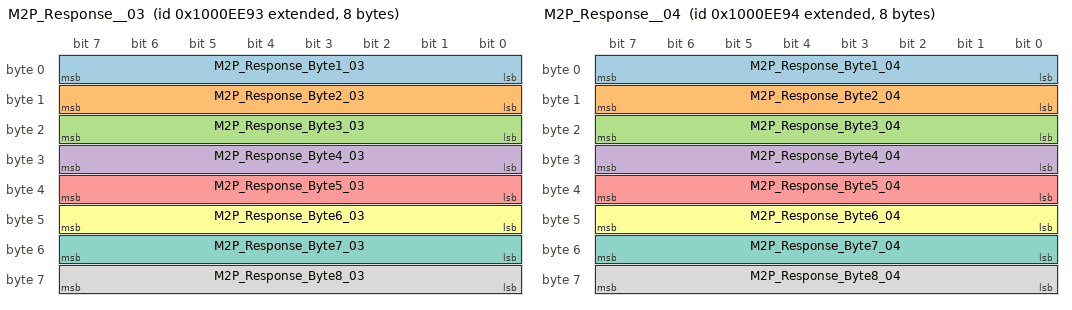
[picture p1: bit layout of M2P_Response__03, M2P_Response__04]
BO_ 2415980179 M2P_Response__03: 8 MBMU
 SG_ M2P_Response_Byte1_03 : 0|8@1+ (1,0) [0|255] ""  PC
 SG_ M2P_Response_Byte2_03 : 8|8@1+ (1,0) [0|255] ""  PC
 SG_ M2P_Response_Byte3_03 : 16|8@1+ (1,0) [0|255] ""  PC
 SG_ M2P_Response_Byte4_03 : 24|8@1+ (1,0) [0|255] ""  PC
 SG_ M2P_Response_Byte5_03 : 32|8@1+ (1,0) [0|255] ""  PC
 SG_ M2P_Response_Byte6_03 : 40|8@1+ (1,0) [0|255] ""  PC
 SG_ M2P_Response_Byte7_03 : 48|8@1+ (1,0) [0|255] ""  PC
 SG_ M2P_Response_Byte8_03 : 56|8@1+ (1,0) [0|255] ""  PC

BO_ 2415980180 M2P_Response__04: 8 MBMU
 SG_ M2P_Response_Byte1_04 : 0|8@1+ (1,0) [0|255] ""  PC
 SG_ M2P_Response_Byte2_04 : 8|8@1+ (1,0) [0|255] ""  PC
 SG_ M2P_Response_Byte3_04 : 16|8@1+ (1,0) [0|255] ""  PC
 SG_ M2P_Response_Byte4_04 : 24|8@1+ (1,0) [0|255] ""  PC
 SG_ M2P_Response_Byte5_04 : 32|8@1+ (1,0) [0|255] ""  PC
 SG_ M2P_Response_Byte6_04 : 40|8@1+ (1,0) [0|255] ""  PC
 SG_ M2P_Response_Byte7_04 : 48|8@1+ (1,0) [0|255] ""  PC
 SG_ M2P_Response_Byte8_04 : 56|8@1+ (1,0) [0|255] ""  PC

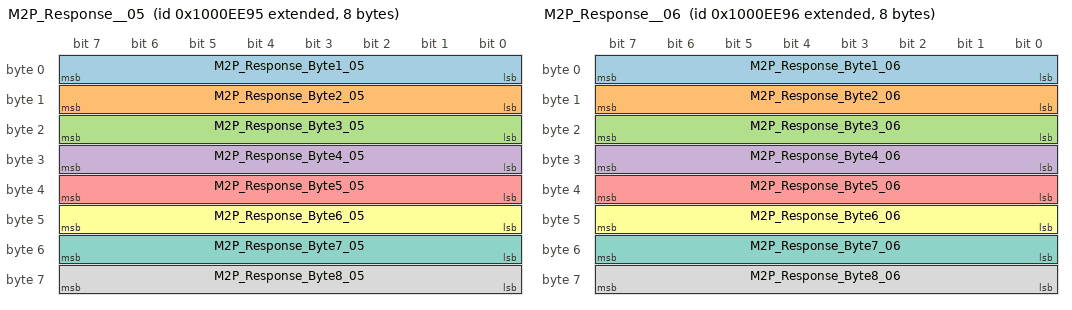
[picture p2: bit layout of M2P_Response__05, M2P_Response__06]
BO_ 2415980181 M2P_Response__05: 8 MBMU
 SG_ M2P_Response_Byte1_05 : 0|8@1+ (1,0) [0|255] ""  PC
 SG_ M2P_Response_Byte2_05 : 8|8@1+ (1,0) [0|255] ""  PC
 SG_ M2P_Response_Byte3_05 : 16|8@1+ (1,0) [0|255] ""  PC
 SG_ M2P_Response_Byte4_05 : 24|8@1+ (1,0) [0|255] ""  PC
 SG_ M2P_Response_Byte5_05 : 32|8@1+ (1,0) [0|255] ""  PC
 SG_ M2P_Response_Byte6_05 : 40|8@1+ (1,0) [0|255] ""  PC
 SG_ M2P_Response_Byte7_05 : 48|8@1+ (1,0) [0|255] ""  PC
 SG_ M2P_Response_Byte8_05 : 56|8@1+ (1,0) [0|255] ""  PC

BO_ 2415980182 M2P_Response__06: 8 MBMU
 SG_ M2P_Response_Byte1_06 : 0|8@1+ (1,0) [0|255] ""  PC
 SG_ M2P_Response_Byte2_06 : 8|8@1+ (1,0) [0|255] ""  PC
 SG_ M2P_Response_Byte3_06 : 16|8@1+ (1,0) [0|255] ""  PC
 SG_ M2P_Response_Byte4_06 : 24|8@1+ (1,0) [0|255] ""  PC
 SG_ M2P_Response_Byte5_06 : 32|8@1+ (1,0) [0|255] ""  PC
 SG_ M2P_Response_Byte6_06 : 40|8@1+ (1,0) [0|255] ""  PC
 SG_ M2P_Response_Byte7_06 : 48|8@1+ (1,0) [0|255] ""  PC
 SG_ M2P_Response_Byte8_06 : 56|8@1+ (1,0) [0|255] ""  PC

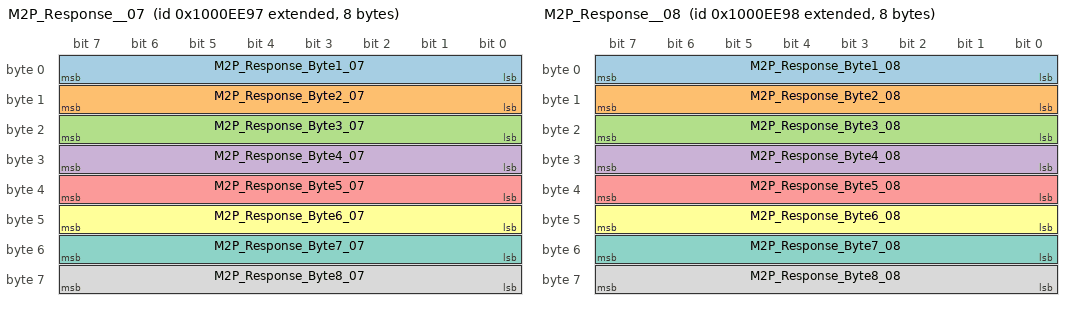
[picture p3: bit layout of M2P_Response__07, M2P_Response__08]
BO_ 2415980183 M2P_Response__07: 8 MBMU
 SG_ M2P_Response_Byte1_07 : 0|8@1+ (1,0) [0|255] ""  PC
 SG_ M2P_Response_Byte2_07 : 8|8@1+ (1,0) [0|255] ""  PC
 SG_ M2P_Response_Byte3_07 : 16|8@1+ (1,0) [0|255] ""  PC
 SG_ M2P_Response_Byte4_07 : 24|8@1+ (1,0) [0|255] ""  PC
 SG_ M2P_Response_Byte5_07 : 32|8@1+ (1,0) [0|255] ""  PC
 SG_ M2P_Response_Byte6_07 : 40|8@1+ (1,0) [0|255] ""  PC
 SG_ M2P_Response_Byte7_07 : 48|8@1+ (1,0) [0|255] ""  PC
 SG_ M2P_Response_Byte8_07 : 56|8@1+ (1,0) [0|255] ""  PC

BO_ 2415980184 M2P_Response__08: 8 MBMU
 SG_ M2P_Response_Byte1_08 : 0|8@1+ (1,0) [0|255] ""  PC
 SG_ M2P_Response_Byte2_08 : 8|8@1+ (1,0) [0|255] ""  PC
 SG_ M2P_Response_Byte3_08 : 16|8@1+ (1,0) [0|255] ""  PC
 SG_ M2P_Response_Byte4_08 : 24|8@1+ (1,0) [0|255] ""  PC
 SG_ M2P_Response_Byte5_08 : 32|8@1+ (1,0) [0|255] ""  PC
 SG_ M2P_Response_Byte6_08 : 40|8@1+ (1,0) [0|255] ""  PC
 SG_ M2P_Response_Byte7_08 : 48|8@1+ (1,0) [0|255] ""  PC
 SG_ M2P_Response_Byte8_08 : 56|8@1+ (1,0) [0|255] ""  PC

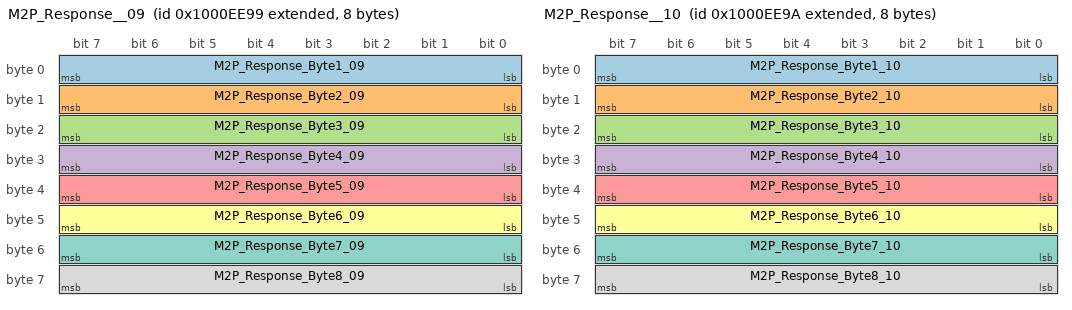
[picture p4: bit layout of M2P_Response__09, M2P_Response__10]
BO_ 2415980185 M2P_Response__09: 8 MBMU
 SG_ M2P_Response_Byte1_09 : 0|8@1+ (1,0) [0|255] ""  PC
 SG_ M2P_Response_Byte2_09 : 8|8@1+ (1,0) [0|255] ""  PC
 SG_ M2P_Response_Byte3_09 : 16|8@1+ (1,0) [0|255] ""  PC
 SG_ M2P_Response_Byte4_09 : 24|8@1+ (1,0) [0|255] ""  PC
 SG_ M2P_Response_Byte5_09 : 32|8@1+ (1,0) [0|255] ""  PC
 SG_ M2P_Response_Byte6_09 : 40|8@1+ (1,0) [0|255] ""  PC
 SG_ M2P_Response_Byte7_09 : 48|8@1+ (1,0) [0|255] ""  PC
 SG_ M2P_Response_Byte8_09 : 56|8@1+ (1,0) [0|255] ""  PC

BO_ 2415980186 M2P_Response__10: 8 MBMU
 SG_ M2P_Response_Byte1_10 : 0|8@1+ (1,0) [0|255] ""  PC
 SG_ M2P_Response_Byte2_10 : 8|8@1+ (1,0) [0|255] ""  PC
 SG_ M2P_Response_Byte3_10 : 16|8@1+ (1,0) [0|255] ""  PC
 SG_ M2P_Response_Byte4_10 : 24|8@1+ (1,0) [0|255] ""  PC
 SG_ M2P_Response_Byte5_10 : 32|8@1+ (1,0) [0|255] ""  PC
 SG_ M2P_Response_Byte6_10 : 40|8@1+ (1,0) [0|255] ""  PC
 SG_ M2P_Response_Byte7_10 : 48|8@1+ (1,0) [0|255] ""  PC
 SG_ M2P_Response_Byte8_10 : 56|8@1+ (1,0) [0|255] ""  PC

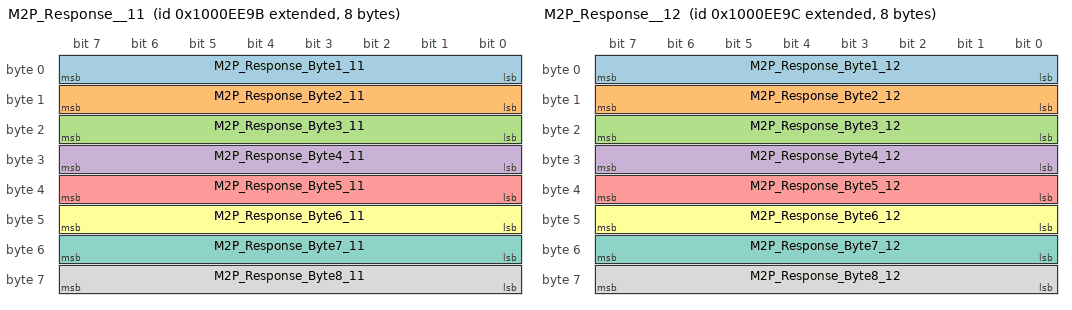
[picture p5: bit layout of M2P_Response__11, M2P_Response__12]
BO_ 2415980187 M2P_Response__11: 8 MBMU
 SG_ M2P_Response_Byte1_11 : 0|8@1+ (1,0) [0|255] ""  PC
 SG_ M2P_Response_Byte2_11 : 8|8@1+ (1,0) [0|255] ""  PC
 SG_ M2P_Response_Byte3_11 : 16|8@1+ (1,0) [0|255] ""  PC
 SG_ M2P_Response_Byte4_11 : 24|8@1+ (1,0) [0|255] ""  PC
 SG_ M2P_Response_Byte5_11 : 32|8@1+ (1,0) [0|255] ""  PC
 SG_ M2P_Response_Byte6_11 : 40|8@1+ (1,0) [0|255] ""  PC
 SG_ M2P_Response_Byte7_11 : 48|8@1+ (1,0) [0|255] ""  PC
 SG_ M2P_Response_Byte8_11 : 56|8@1+ (1,0) [0|255] ""  PC

BO_ 2415980188 M2P_Response__12: 8 MBMU
 SG_ M2P_Response_Byte1_12 : 0|8@1+ (1,0) [0|255] ""  PC
 SG_ M2P_Response_Byte2_12 : 8|8@1+ (1,0) [0|255] ""  PC
 SG_ M2P_Response_Byte3_12 : 16|8@1+ (1,0) [0|255] ""  PC
 SG_ M2P_Response_Byte4_12 : 24|8@1+ (1,0) [0|255] ""  PC
 SG_ M2P_Response_Byte5_12 : 32|8@1+ (1,0) [0|255] ""  PC
 SG_ M2P_Response_Byte6_12 : 40|8@1+ (1,0) [0|255] ""  PC
 SG_ M2P_Response_Byte7_12 : 48|8@1+ (1,0) [0|255] ""  PC
 SG_ M2P_Response_Byte8_12 : 56|8@1+ (1,0) [0|255] ""  PC

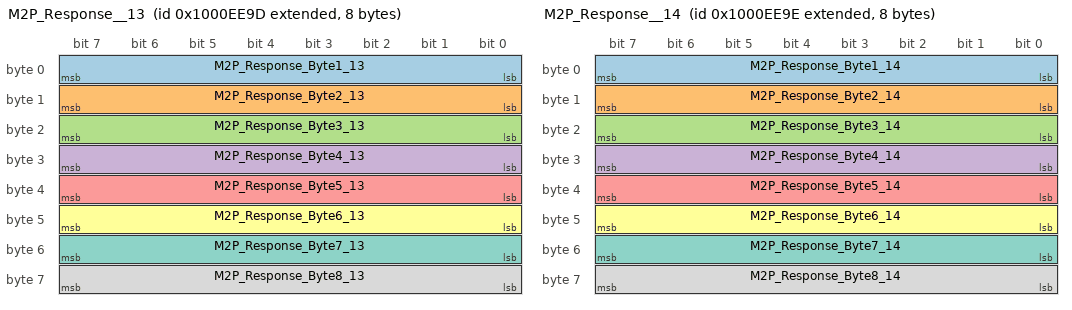
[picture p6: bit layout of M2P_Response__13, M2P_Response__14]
BO_ 2415980189 M2P_Response__13: 8 MBMU
 SG_ M2P_Response_Byte1_13 : 0|8@1+ (1,0) [0|255] ""  PC
 SG_ M2P_Response_Byte2_13 : 8|8@1+ (1,0) [0|255] ""  PC
 SG_ M2P_Response_Byte3_13 : 16|8@1+ (1,0) [0|255] ""  PC
 SG_ M2P_Response_Byte4_13 : 24|8@1+ (1,0) [0|255] ""  PC
 SG_ M2P_Response_Byte5_13 : 32|8@1+ (1,0) [0|255] ""  PC
 SG_ M2P_Response_Byte6_13 : 40|8@1+ (1,0) [0|255] ""  PC
 SG_ M2P_Response_Byte7_13 : 48|8@1+ (1,0) [0|255] ""  PC
 SG_ M2P_Response_Byte8_13 : 56|8@1+ (1,0) [0|255] ""  PC

BO_ 2415980190 M2P_Response__14: 8 MBMU
 SG_ M2P_Response_Byte1_14 : 0|8@1+ (1,0) [0|255] ""  PC
 SG_ M2P_Response_Byte2_14 : 8|8@1+ (1,0) [0|255] ""  PC
 SG_ M2P_Response_Byte3_14 : 16|8@1+ (1,0) [0|255] ""  PC
 SG_ M2P_Response_Byte4_14 : 24|8@1+ (1,0) [0|255] ""  PC
 SG_ M2P_Response_Byte5_14 : 32|8@1+ (1,0) [0|255] ""  PC
 SG_ M2P_Response_Byte6_14 : 40|8@1+ (1,0) [0|255] ""  PC
 SG_ M2P_Response_Byte7_14 : 48|8@1+ (1,0) [0|255] ""  PC
 SG_ M2P_Response_Byte8_14 : 56|8@1+ (1,0) [0|255] ""  PC

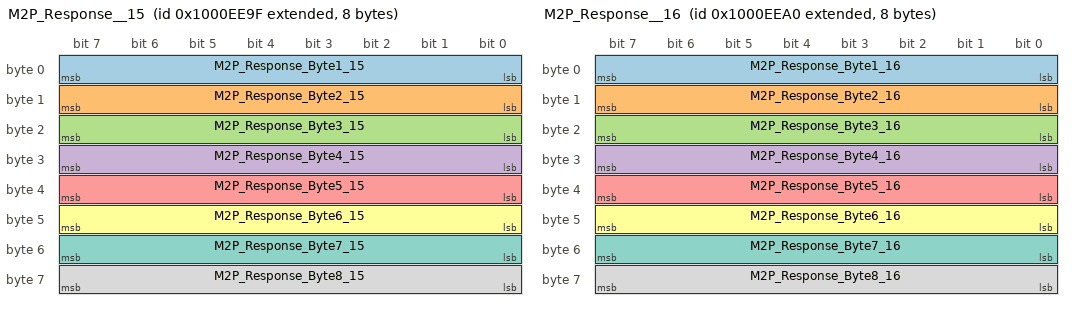
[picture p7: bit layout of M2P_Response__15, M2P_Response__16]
BO_ 2415980191 M2P_Response__15: 8 MBMU
 SG_ M2P_Response_Byte1_15 : 0|8@1+ (1,0) [0|255] ""  PC
 SG_ M2P_Response_Byte2_15 : 8|8@1+ (1,0) [0|255] ""  PC
 SG_ M2P_Response_Byte3_15 : 16|8@1+ (1,0) [0|255] ""  PC
 SG_ M2P_Response_Byte4_15 : 24|8@1+ (1,0) [0|255] ""  PC
 SG_ M2P_Response_Byte5_15 : 32|8@1+ (1,0) [0|255] ""  PC
 SG_ M2P_Response_Byte6_15 : 40|8@1+ (1,0) [0|255] ""  PC
 SG_ M2P_Response_Byte7_15 : 48|8@1+ (1,0) [0|255] ""  PC
 SG_ M2P_Response_Byte8_15 : 56|8@1+ (1,0) [0|255] ""  PC

BO_ 2415980192 M2P_Response__16: 8 MBMU
 SG_ M2P_Response_Byte1_16 : 0|8@1+ (1,0) [0|255] ""  PC
 SG_ M2P_Response_Byte2_16 : 8|8@1+ (1,0) [0|255] ""  PC
 SG_ M2P_Response_Byte3_16 : 16|8@1+ (1,0) [0|255] ""  PC
 SG_ M2P_Response_Byte4_16 : 24|8@1+ (1,0) [0|255] ""  PC
 SG_ M2P_Response_Byte5_16 : 32|8@1+ (1,0) [0|255] ""  PC
 SG_ M2P_Response_Byte6_16 : 40|8@1+ (1,0) [0|255] ""  PC
 SG_ M2P_Response_Byte7_16 : 48|8@1+ (1,0) [0|255] ""  PC
 SG_ M2P_Response_Byte8_16 : 56|8@1+ (1,0) [0|255] ""  PC

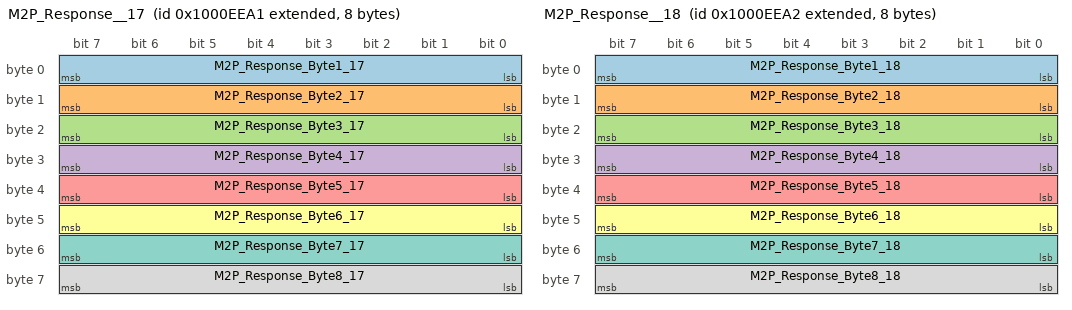
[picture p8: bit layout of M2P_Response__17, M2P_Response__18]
BO_ 2415980193 M2P_Response__17: 8 MBMU
 SG_ M2P_Response_Byte1_17 : 0|8@1+ (1,0) [0|255] ""  PC
 SG_ M2P_Response_Byte2_17 : 8|8@1+ (1,0) [0|255] ""  PC
 SG_ M2P_Response_Byte3_17 : 16|8@1+ (1,0) [0|255] ""  PC
 SG_ M2P_Response_Byte4_17 : 24|8@1+ (1,0) [0|255] ""  PC
 SG_ M2P_Response_Byte5_17 : 32|8@1+ (1,0) [0|255] ""  PC
 SG_ M2P_Response_Byte6_17 : 40|8@1+ (1,0) [0|255] ""  PC
 SG_ M2P_Response_Byte7_17 : 48|8@1+ (1,0) [0|255] ""  PC
 SG_ M2P_Response_Byte8_17 : 56|8@1+ (1,0) [0|255] ""  PC

BO_ 2415980194 M2P_Response__18: 8 MBMU
 SG_ M2P_Response_Byte1_18 : 0|8@1+ (1,0) [0|255] ""  PC
 SG_ M2P_Response_Byte2_18 : 8|8@1+ (1,0) [0|255] ""  PC
 SG_ M2P_Response_Byte3_18 : 16|8@1+ (1,0) [0|255] ""  PC
 SG_ M2P_Response_Byte4_18 : 24|8@1+ (1,0) [0|255] ""  PC
 SG_ M2P_Response_Byte5_18 : 32|8@1+ (1,0) [0|255] ""  PC
 SG_ M2P_Response_Byte6_18 : 40|8@1+ (1,0) [0|255] ""  PC
 SG_ M2P_Response_Byte7_18 : 48|8@1+ (1,0) [0|255] ""  PC
 SG_ M2P_Response_Byte8_18 : 56|8@1+ (1,0) [0|255] ""  PC

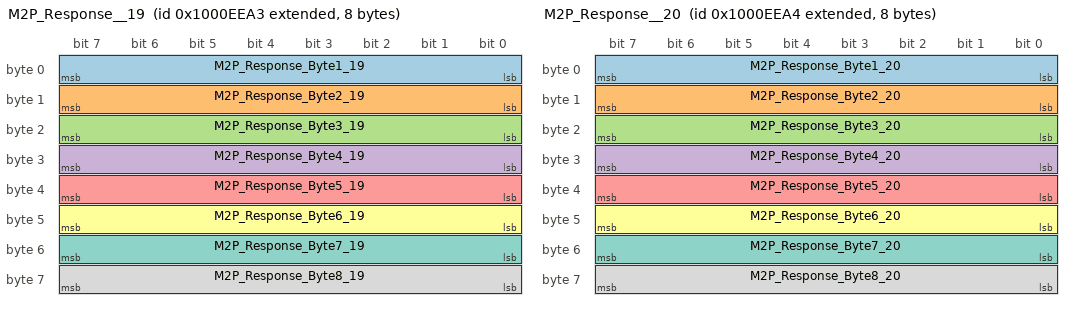
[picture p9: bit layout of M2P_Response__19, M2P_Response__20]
BO_ 2415980195 M2P_Response__19: 8 MBMU
 SG_ M2P_Response_Byte1_19 : 0|8@1+ (1,0) [0|255] ""  PC
 SG_ M2P_Response_Byte2_19 : 8|8@1+ (1,0) [0|255] ""  PC
 SG_ M2P_Response_Byte3_19 : 16|8@1+ (1,0) [0|255] ""  PC
 SG_ M2P_Response_Byte4_19 : 24|8@1+ (1,0) [0|255] ""  PC
 SG_ M2P_Response_Byte5_19 : 32|8@1+ (1,0) [0|255] ""  PC
 SG_ M2P_Response_Byte6_19 : 40|8@1+ (1,0) [0|255] ""  PC
 SG_ M2P_Response_Byte7_19 : 48|8@1+ (1,0) [0|255] ""  PC
 SG_ M2P_Response_Byte8_19 : 56|8@1+ (1,0) [0|255] ""  PC

BO_ 2415980196 M2P_Response__20: 8 MBMU
 SG_ M2P_Response_Byte1_20 : 0|8@1+ (1,0) [0|255] ""  PC
 SG_ M2P_Response_Byte2_20 : 8|8@1+ (1,0) [0|255] ""  PC
 SG_ M2P_Response_Byte3_20 : 16|8@1+ (1,0) [0|255] ""  PC
 SG_ M2P_Response_Byte4_20 : 24|8@1+ (1,0) [0|255] ""  PC
 SG_ M2P_Response_Byte5_20 : 32|8@1+ (1,0) [0|255] ""  PC
 SG_ M2P_Response_Byte6_20 : 40|8@1+ (1,0) [0|255] ""  PC
 SG_ M2P_Response_Byte7_20 : 48|8@1+ (1,0) [0|255] ""  PC
 SG_ M2P_Response_Byte8_20 : 56|8@1+ (1,0) [0|255] ""  PC

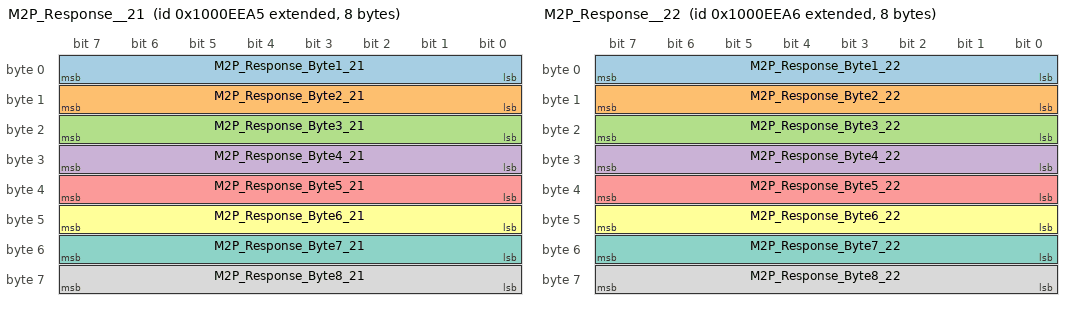
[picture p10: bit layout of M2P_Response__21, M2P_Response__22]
BO_ 2415980197 M2P_Response__21: 8 MBMU
 SG_ M2P_Response_Byte1_21 : 0|8@1+ (1,0) [0|255] ""  PC
 SG_ M2P_Response_Byte2_21 : 8|8@1+ (1,0) [0|255] ""  PC
 SG_ M2P_Response_Byte3_21 : 16|8@1+ (1,0) [0|255] ""  PC
 SG_ M2P_Response_Byte4_21 : 24|8@1+ (1,0) [0|255] ""  PC
 SG_ M2P_Response_Byte5_21 : 32|8@1+ (1,0) [0|255] ""  PC
 SG_ M2P_Response_Byte6_21 : 40|8@1+ (1,0) [0|255] ""  PC
 SG_ M2P_Response_Byte7_21 : 48|8@1+ (1,0) [0|255] ""  PC
 SG_ M2P_Response_Byte8_21 : 56|8@1+ (1,0) [0|255] ""  PC

BO_ 2415980198 M2P_Response__22: 8 MBMU
 SG_ M2P_Response_Byte1_22 : 0|8@1+ (1,0) [0|255] ""  PC
 SG_ M2P_Response_Byte2_22 : 8|8@1+ (1,0) [0|255] ""  PC
 SG_ M2P_Response_Byte3_22 : 16|8@1+ (1,0) [0|255] ""  PC
 SG_ M2P_Response_Byte4_22 : 24|8@1+ (1,0) [0|255] ""  PC
 SG_ M2P_Response_Byte5_22 : 32|8@1+ (1,0) [0|255] ""  PC
 SG_ M2P_Response_Byte6_22 : 40|8@1+ (1,0) [0|255] ""  PC
 SG_ M2P_Response_Byte7_22 : 48|8@1+ (1,0) [0|255] ""  PC
 SG_ M2P_Response_Byte8_22 : 56|8@1+ (1,0) [0|255] ""  PC

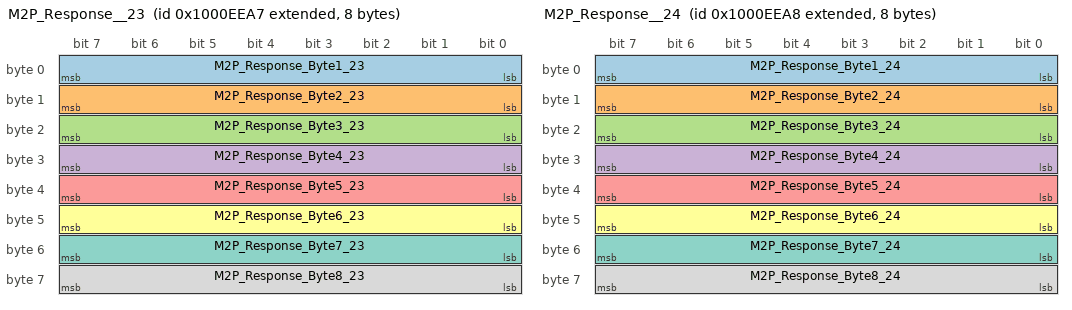
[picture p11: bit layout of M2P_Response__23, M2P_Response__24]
BO_ 2415980199 M2P_Response__23: 8 MBMU
 SG_ M2P_Response_Byte1_23 : 0|8@1+ (1,0) [0|255] ""  PC
 SG_ M2P_Response_Byte2_23 : 8|8@1+ (1,0) [0|255] ""  PC
 SG_ M2P_Response_Byte3_23 : 16|8@1+ (1,0) [0|255] ""  PC
 SG_ M2P_Response_Byte4_23 : 24|8@1+ (1,0) [0|255] ""  PC
 SG_ M2P_Response_Byte5_23 : 32|8@1+ (1,0) [0|255] ""  PC
 SG_ M2P_Response_Byte6_23 : 40|8@1+ (1,0) [0|255] ""  PC
 SG_ M2P_Response_Byte7_23 : 48|8@1+ (1,0) [0|255] ""  PC
 SG_ M2P_Response_Byte8_23 : 56|8@1+ (1,0) [0|255] ""  PC

BO_ 2415980200 M2P_Response__24: 8 MBMU
 SG_ M2P_Response_Byte1_24 : 0|8@1+ (1,0) [0|255] ""  PC
 SG_ M2P_Response_Byte2_24 : 8|8@1+ (1,0) [0|255] ""  PC
 SG_ M2P_Response_Byte3_24 : 16|8@1+ (1,0) [0|255] ""  PC
 SG_ M2P_Response_Byte4_24 : 24|8@1+ (1,0) [0|255] ""  PC
 SG_ M2P_Response_Byte5_24 : 32|8@1+ (1,0) [0|255] ""  PC
 SG_ M2P_Response_Byte6_24 : 40|8@1+ (1,0) [0|255] ""  PC
 SG_ M2P_Response_Byte7_24 : 48|8@1+ (1,0) [0|255] ""  PC
 SG_ M2P_Response_Byte8_24 : 56|8@1+ (1,0) [0|255] ""  PC

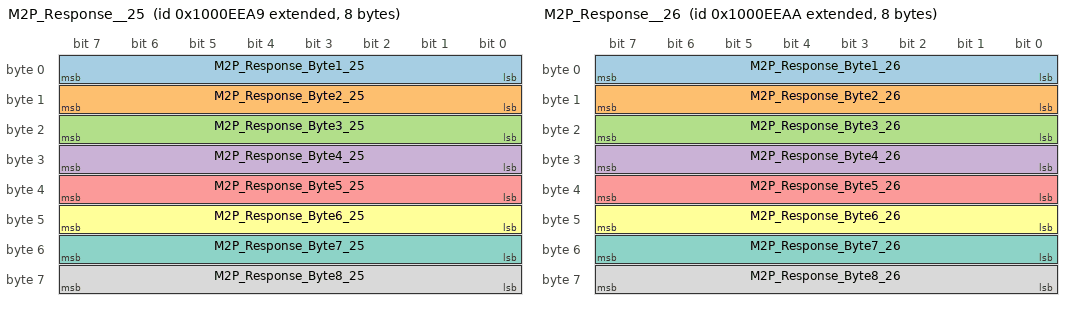
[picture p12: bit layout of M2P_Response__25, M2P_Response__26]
BO_ 2415980201 M2P_Response__25: 8 MBMU
 SG_ M2P_Response_Byte1_25 : 0|8@1+ (1,0) [0|255] ""  PC
 SG_ M2P_Response_Byte2_25 : 8|8@1+ (1,0) [0|255] ""  PC
 SG_ M2P_Response_Byte3_25 : 16|8@1+ (1,0) [0|255] ""  PC
 SG_ M2P_Response_Byte4_25 : 24|8@1+ (1,0) [0|255] ""  PC
 SG_ M2P_Response_Byte5_25 : 32|8@1+ (1,0) [0|255] ""  PC
 SG_ M2P_Response_Byte6_25 : 40|8@1+ (1,0) [0|255] ""  PC
 SG_ M2P_Response_Byte7_25 : 48|8@1+ (1,0) [0|255] ""  PC
 SG_ M2P_Response_Byte8_25 : 56|8@1+ (1,0) [0|255] ""  PC

BO_ 2415980202 M2P_Response__26: 8 MBMU
 SG_ M2P_Response_Byte1_26 : 0|8@1+ (1,0) [0|255] ""  PC
 SG_ M2P_Response_Byte2_26 : 8|8@1+ (1,0) [0|255] ""  PC
 SG_ M2P_Response_Byte3_26 : 16|8@1+ (1,0) [0|255] ""  PC
 SG_ M2P_Response_Byte4_26 : 24|8@1+ (1,0) [0|255] ""  PC
 SG_ M2P_Response_Byte5_26 : 32|8@1+ (1,0) [0|255] ""  PC
 SG_ M2P_Response_Byte6_26 : 40|8@1+ (1,0) [0|255] ""  PC
 SG_ M2P_Response_Byte7_26 : 48|8@1+ (1,0) [0|255] ""  PC
 SG_ M2P_Response_Byte8_26 : 56|8@1+ (1,0) [0|255] ""  PC

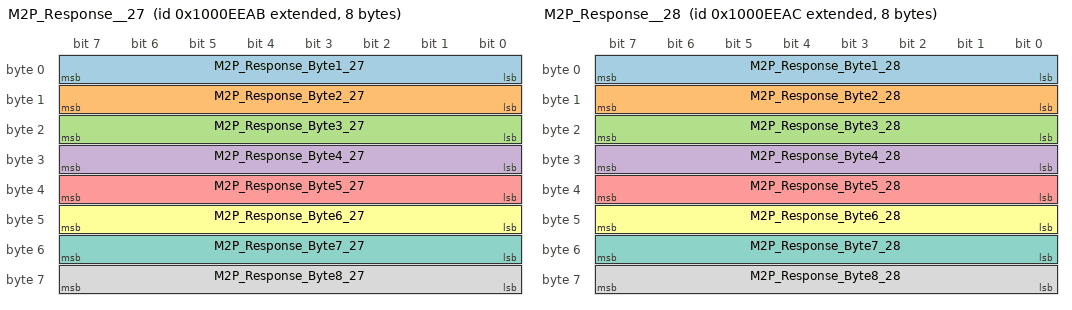
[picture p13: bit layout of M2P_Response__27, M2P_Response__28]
BO_ 2415980203 M2P_Response__27: 8 MBMU
 SG_ M2P_Response_Byte1_27 : 0|8@1+ (1,0) [0|255] ""  PC
 SG_ M2P_Response_Byte2_27 : 8|8@1+ (1,0) [0|255] ""  PC
 SG_ M2P_Response_Byte3_27 : 16|8@1+ (1,0) [0|255] ""  PC
 SG_ M2P_Response_Byte4_27 : 24|8@1+ (1,0) [0|255] ""  PC
 SG_ M2P_Response_Byte5_27 : 32|8@1+ (1,0) [0|255] ""  PC
 SG_ M2P_Response_Byte6_27 : 40|8@1+ (1,0) [0|255] ""  PC
 SG_ M2P_Response_Byte7_27 : 48|8@1+ (1,0) [0|255] ""  PC
 SG_ M2P_Response_Byte8_27 : 56|8@1+ (1,0) [0|255] ""  PC

BO_ 2415980204 M2P_Response__28: 8 MBMU
 SG_ M2P_Response_Byte1_28 : 0|8@1+ (1,0) [0|255] ""  PC
 SG_ M2P_Response_Byte2_28 : 8|8@1+ (1,0) [0|255] ""  PC
 SG_ M2P_Response_Byte3_28 : 16|8@1+ (1,0) [0|255] ""  PC
 SG_ M2P_Response_Byte4_28 : 24|8@1+ (1,0) [0|255] ""  PC
 SG_ M2P_Response_Byte5_28 : 32|8@1+ (1,0) [0|255] ""  PC
 SG_ M2P_Response_Byte6_28 : 40|8@1+ (1,0) [0|255] ""  PC
 SG_ M2P_Response_Byte7_28 : 48|8@1+ (1,0) [0|255] ""  PC
 SG_ M2P_Response_Byte8_28 : 56|8@1+ (1,0) [0|255] ""  PC

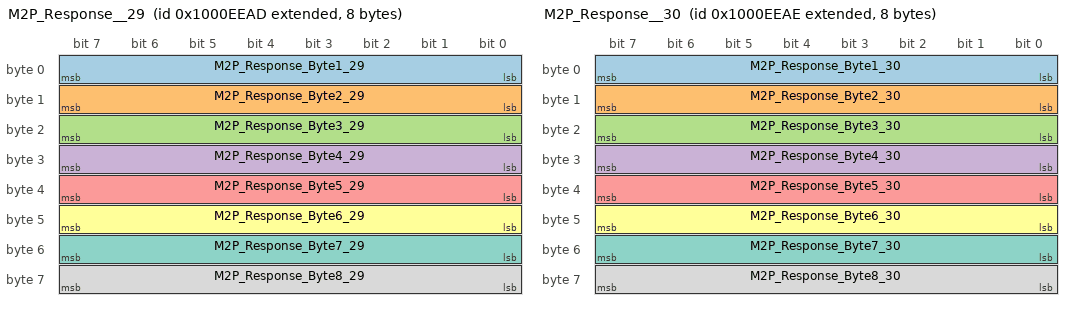
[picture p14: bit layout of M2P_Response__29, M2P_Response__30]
BO_ 2415980205 M2P_Response__29: 8 MBMU
 SG_ M2P_Response_Byte1_29 : 0|8@1+ (1,0) [0|255] ""  PC
 SG_ M2P_Response_Byte2_29 : 8|8@1+ (1,0) [0|255] ""  PC
 SG_ M2P_Response_Byte3_29 : 16|8@1+ (1,0) [0|255] ""  PC
 SG_ M2P_Response_Byte4_29 : 24|8@1+ (1,0) [0|255] ""  PC
 SG_ M2P_Response_Byte5_29 : 32|8@1+ (1,0) [0|255] ""  PC
 SG_ M2P_Response_Byte6_29 : 40|8@1+ (1,0) [0|255] ""  PC
 SG_ M2P_Response_Byte7_29 : 48|8@1+ (1,0) [0|255] ""  PC
 SG_ M2P_Response_Byte8_29 : 56|8@1+ (1,0) [0|255] ""  PC

BO_ 2415980206 M2P_Response__30: 8 MBMU
 SG_ M2P_Response_Byte1_30 : 0|8@1+ (1,0) [0|255] ""  PC
 SG_ M2P_Response_Byte2_30 : 8|8@1+ (1,0) [0|255] ""  PC
 SG_ M2P_Response_Byte3_30 : 16|8@1+ (1,0) [0|255] ""  PC
 SG_ M2P_Response_Byte4_30 : 24|8@1+ (1,0) [0|255] ""  PC
 SG_ M2P_Response_Byte5_30 : 32|8@1+ (1,0) [0|255] ""  PC
 SG_ M2P_Response_Byte6_30 : 40|8@1+ (1,0) [0|255] ""  PC
 SG_ M2P_Response_Byte7_30 : 48|8@1+ (1,0) [0|255] ""  PC
 SG_ M2P_Response_Byte8_30 : 56|8@1+ (1,0) [0|255] ""  PC

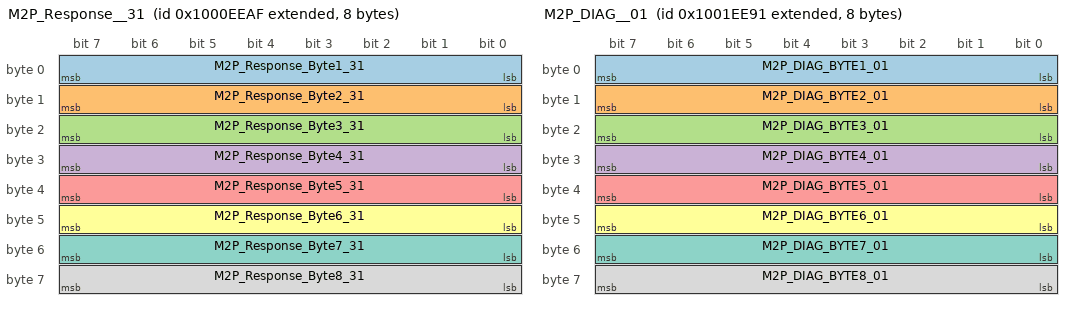
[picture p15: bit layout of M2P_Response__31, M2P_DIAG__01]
BO_ 2415980207 M2P_Response__31: 8 MBMU
 SG_ M2P_Response_Byte1_31 : 0|8@1+ (1,0) [0|255] ""  PC
 SG_ M2P_Response_Byte2_31 : 8|8@1+ (1,0) [0|255] ""  PC
 SG_ M2P_Response_Byte3_31 : 16|8@1+ (1,0) [0|255] ""  PC
 SG_ M2P_Response_Byte4_31 : 24|8@1+ (1,0) [0|255] ""  PC
 SG_ M2P_Response_Byte5_31 : 32|8@1+ (1,0) [0|255] ""  PC
 SG_ M2P_Response_Byte6_31 : 40|8@1+ (1,0) [0|255] ""  PC
 SG_ M2P_Response_Byte7_31 : 48|8@1+ (1,0) [0|255] ""  PC
 SG_ M2P_Response_Byte8_31 : 56|8@1+ (1,0) [0|255] ""  PC

BO_ 2416045713 M2P_DIAG__01: 8 MBMU
 SG_ M2P_DIAG_BYTE1_01 : 0|8@1+ (1,0) [0|255] ""  PC
 SG_ M2P_DIAG_BYTE2_01 : 8|8@1+ (1,0) [0|255] ""  PC
 SG_ M2P_DIAG_BYTE3_01 : 16|8@1+ (1,0) [0|255] ""  PC
 SG_ M2P_DIAG_BYTE4_01 : 24|8@1+ (1,0) [0|255] ""  PC
 SG_ M2P_DIAG_BYTE5_01 : 32|8@1+ (1,0) [0|255] ""  PC
 SG_ M2P_DIAG_BYTE6_01 : 40|8@1+ (1,0) [0|255] ""  PC
 SG_ M2P_DIAG_BYTE7_01 : 48|8@1+ (1,0) [0|255] ""  PC
 SG_ M2P_DIAG_BYTE8_01 : 56|8@1+ (1,0) [0|255] ""  PC

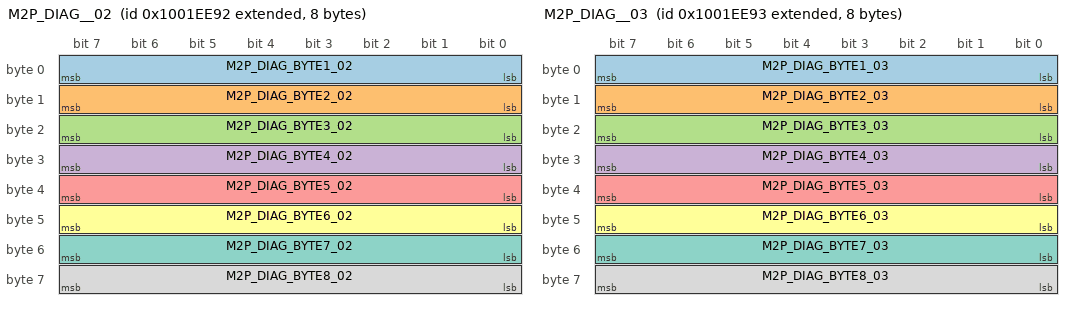
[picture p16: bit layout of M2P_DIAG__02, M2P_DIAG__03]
BO_ 2416045714 M2P_DIAG__02: 8 MBMU
 SG_ M2P_DIAG_BYTE1_02 : 0|8@1+ (1,0) [0|255] ""  PC
 SG_ M2P_DIAG_BYTE2_02 : 8|8@1+ (1,0) [0|255] ""  PC
 SG_ M2P_DIAG_BYTE3_02 : 16|8@1+ (1,0) [0|255] ""  PC
 SG_ M2P_DIAG_BYTE4_02 : 24|8@1+ (1,0) [0|255] ""  PC
 SG_ M2P_DIAG_BYTE5_02 : 32|8@1+ (1,0) [0|255] ""  PC
 SG_ M2P_DIAG_BYTE6_02 : 40|8@1+ (1,0) [0|255] ""  PC
 SG_ M2P_DIAG_BYTE7_02 : 48|8@1+ (1,0) [0|255] ""  PC
 SG_ M2P_DIAG_BYTE8_02 : 56|8@1+ (1,0) [0|255] ""  PC

BO_ 2416045715 M2P_DIAG__03: 8 MBMU
 SG_ M2P_DIAG_BYTE1_03 : 0|8@1+ (1,0) [0|255] ""  PC
 SG_ M2P_DIAG_BYTE2_03 : 8|8@1+ (1,0) [0|255] ""  PC
 SG_ M2P_DIAG_BYTE3_03 : 16|8@1+ (1,0) [0|255] ""  PC
 SG_ M2P_DIAG_BYTE4_03 : 24|8@1+ (1,0) [0|255] ""  PC
 SG_ M2P_DIAG_BYTE5_03 : 32|8@1+ (1,0) [0|255] ""  PC
 SG_ M2P_DIAG_BYTE6_03 : 40|8@1+ (1,0) [0|255] ""  PC
 SG_ M2P_DIAG_BYTE7_03 : 48|8@1+ (1,0) [0|255] ""  PC
 SG_ M2P_DIAG_BYTE8_03 : 56|8@1+ (1,0) [0|255] ""  PC

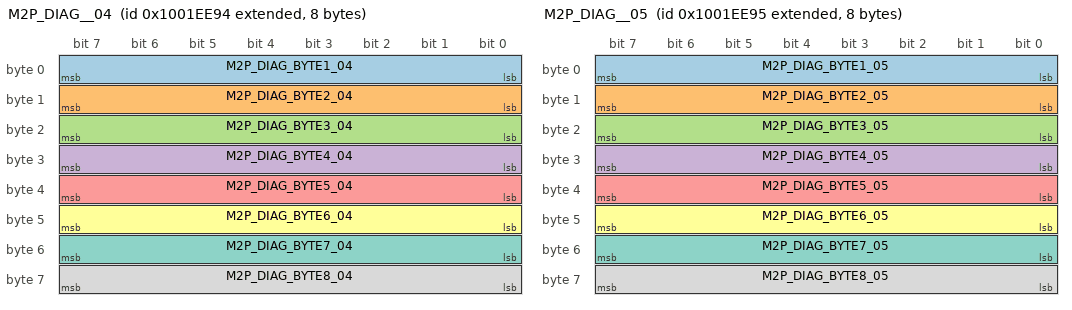
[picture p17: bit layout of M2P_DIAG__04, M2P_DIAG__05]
BO_ 2416045716 M2P_DIAG__04: 8 MBMU
 SG_ M2P_DIAG_BYTE1_04 : 0|8@1+ (1,0) [0|255] ""  PC
 SG_ M2P_DIAG_BYTE2_04 : 8|8@1+ (1,0) [0|255] ""  PC
 SG_ M2P_DIAG_BYTE3_04 : 16|8@1+ (1,0) [0|255] ""  PC
 SG_ M2P_DIAG_BYTE4_04 : 24|8@1+ (1,0) [0|255] ""  PC
 SG_ M2P_DIAG_BYTE5_04 : 32|8@1+ (1,0) [0|255] ""  PC
 SG_ M2P_DIAG_BYTE6_04 : 40|8@1+ (1,0) [0|255] ""  PC
 SG_ M2P_DIAG_BYTE7_04 : 48|8@1+ (1,0) [0|255] ""  PC
 SG_ M2P_DIAG_BYTE8_04 : 56|8@1+ (1,0) [0|255] ""  PC

BO_ 2416045717 M2P_DIAG__05: 8 MBMU
 SG_ M2P_DIAG_BYTE1_05 : 0|8@1+ (1,0) [0|255] ""  PC
 SG_ M2P_DIAG_BYTE2_05 : 8|8@1+ (1,0) [0|255] ""  PC
 SG_ M2P_DIAG_BYTE3_05 : 16|8@1+ (1,0) [0|255] ""  PC
 SG_ M2P_DIAG_BYTE4_05 : 24|8@1+ (1,0) [0|255] ""  PC
 SG_ M2P_DIAG_BYTE5_05 : 32|8@1+ (1,0) [0|255] ""  PC
 SG_ M2P_DIAG_BYTE6_05 : 40|8@1+ (1,0) [0|255] ""  PC
 SG_ M2P_DIAG_BYTE7_05 : 48|8@1+ (1,0) [0|255] ""  PC
 SG_ M2P_DIAG_BYTE8_05 : 56|8@1+ (1,0) [0|255] ""  PC

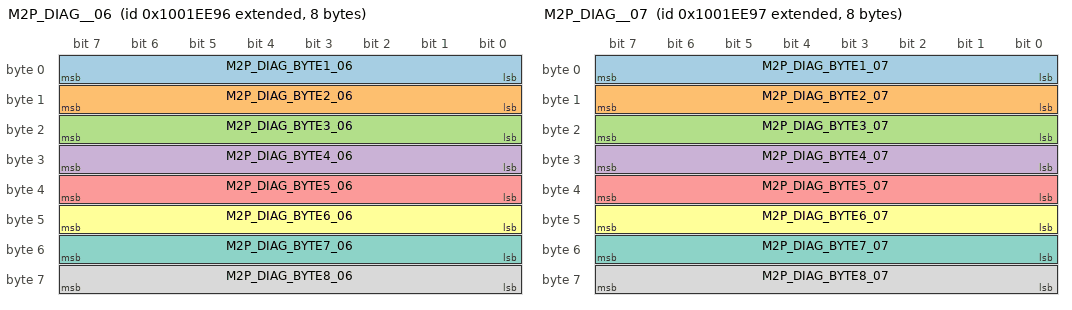
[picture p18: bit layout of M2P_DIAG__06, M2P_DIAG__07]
BO_ 2416045718 M2P_DIAG__06: 8 MBMU
 SG_ M2P_DIAG_BYTE1_06 : 0|8@1+ (1,0) [0|255] ""  PC
 SG_ M2P_DIAG_BYTE2_06 : 8|8@1+ (1,0) [0|255] ""  PC
 SG_ M2P_DIAG_BYTE3_06 : 16|8@1+ (1,0) [0|255] ""  PC
 SG_ M2P_DIAG_BYTE4_06 : 24|8@1+ (1,0) [0|255] ""  PC
 SG_ M2P_DIAG_BYTE5_06 : 32|8@1+ (1,0) [0|255] ""  PC
 SG_ M2P_DIAG_BYTE6_06 : 40|8@1+ (1,0) [0|255] ""  PC
 SG_ M2P_DIAG_BYTE7_06 : 48|8@1+ (1,0) [0|255] ""  PC
 SG_ M2P_DIAG_BYTE8_06 : 56|8@1+ (1,0) [0|255] ""  PC

BO_ 2416045719 M2P_DIAG__07: 8 MBMU
 SG_ M2P_DIAG_BYTE1_07 : 0|8@1+ (1,0) [0|255] ""  PC
 SG_ M2P_DIAG_BYTE2_07 : 8|8@1+ (1,0) [0|255] ""  PC
 SG_ M2P_DIAG_BYTE3_07 : 16|8@1+ (1,0) [0|255] ""  PC
 SG_ M2P_DIAG_BYTE4_07 : 24|8@1+ (1,0) [0|255] ""  PC
 SG_ M2P_DIAG_BYTE5_07 : 32|8@1+ (1,0) [0|255] ""  PC
 SG_ M2P_DIAG_BYTE6_07 : 40|8@1+ (1,0) [0|255] ""  PC
 SG_ M2P_DIAG_BYTE7_07 : 48|8@1+ (1,0) [0|255] ""  PC
 SG_ M2P_DIAG_BYTE8_07 : 56|8@1+ (1,0) [0|255] ""  PC

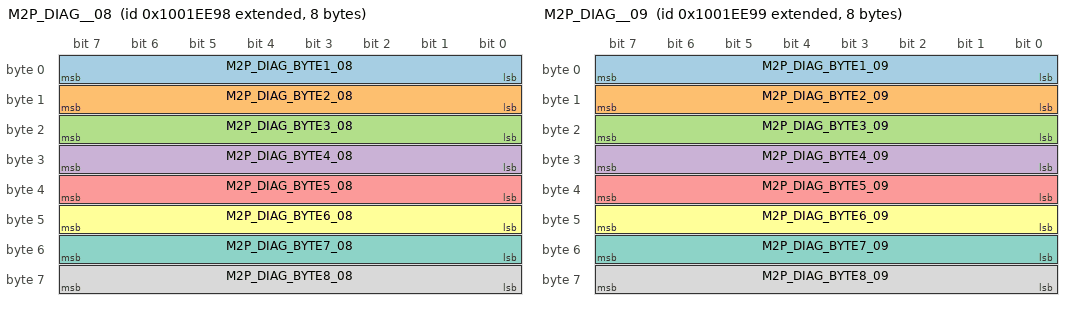
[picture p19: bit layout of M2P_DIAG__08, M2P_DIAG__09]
BO_ 2416045720 M2P_DIAG__08: 8 MBMU
 SG_ M2P_DIAG_BYTE1_08 : 0|8@1+ (1,0) [0|255] ""  PC
 SG_ M2P_DIAG_BYTE2_08 : 8|8@1+ (1,0) [0|255] ""  PC
 SG_ M2P_DIAG_BYTE3_08 : 16|8@1+ (1,0) [0|255] ""  PC
 SG_ M2P_DIAG_BYTE4_08 : 24|8@1+ (1,0) [0|255] ""  PC
 SG_ M2P_DIAG_BYTE5_08 : 32|8@1+ (1,0) [0|255] ""  PC
 SG_ M2P_DIAG_BYTE6_08 : 40|8@1+ (1,0) [0|255] ""  PC
 SG_ M2P_DIAG_BYTE7_08 : 48|8@1+ (1,0) [0|255] ""  PC
 SG_ M2P_DIAG_BYTE8_08 : 56|8@1+ (1,0) [0|255] ""  PC

BO_ 2416045721 M2P_DIAG__09: 8 MBMU
 SG_ M2P_DIAG_BYTE1_09 : 0|8@1+ (1,0) [0|255] ""  PC
 SG_ M2P_DIAG_BYTE2_09 : 8|8@1+ (1,0) [0|255] ""  PC
 SG_ M2P_DIAG_BYTE3_09 : 16|8@1+ (1,0) [0|255] ""  PC
 SG_ M2P_DIAG_BYTE4_09 : 24|8@1+ (1,0) [0|255] ""  PC
 SG_ M2P_DIAG_BYTE5_09 : 32|8@1+ (1,0) [0|255] ""  PC
 SG_ M2P_DIAG_BYTE6_09 : 40|8@1+ (1,0) [0|255] ""  PC
 SG_ M2P_DIAG_BYTE7_09 : 48|8@1+ (1,0) [0|255] ""  PC
 SG_ M2P_DIAG_BYTE8_09 : 56|8@1+ (1,0) [0|255] ""  PC

BO_ 2416045722 M2P_DIAG__10: 8 MBMU
 SG_ M2P_DIAG_BYTE1_10 : 0|8@1+ (1,0) [0|255] ""  PC
 SG_ M2P_DIAG_BYTE2_10 : 8|8@1+ (1,0) [0|255] ""  PC
 SG_ M2P_DIAG_BYTE3_10 : 16|8@1+ (1,0) [0|255] ""  PC
 SG_ M2P_DIAG_BYTE4_10 : 24|8@1+ (1,0) [0|255] ""  PC
 SG_ M2P_DIAG_BYTE5_10 : 32|8@1+ (1,0) [0|255] ""  PC
 SG_ M2P_DIAG_BYTE6_10 : 40|8@1+ (1,0) [0|255] ""  PC
 SG_ M2P_DIAG_BYTE7_10 : 48|8@1+ (1,0) [0|255] ""  PC
 SG_ M2P_DIAG_BYTE8_10 : 56|8@1+ (1,0) [0|255] ""  PC

BO_ 2416045723 M2P_DIAG__11: 8 MBMU
 SG_ M2P_DIAG_BYTE1_11 : 0|8@1+ (1,0) [0|255] ""  PC
 SG_ M2P_DIAG_BYTE2_11 : 8|8@1+ (1,0) [0|255] ""  PC
 SG_ M2P_DIAG_BYTE3_11 : 16|8@1+ (1,0) [0|255] ""  PC
 SG_ M2P_DIAG_BYTE4_11 : 24|8@1+ (1,0) [0|255] ""  PC
 SG_ M2P_DIAG_BYTE5_11 : 32|8@1+ (1,0) [0|255] ""  PC
 SG_ M2P_DIAG_BYTE6_11 : 40|8@1+ (1,0) [0|255] ""  PC
 SG_ M2P_DIAG_BYTE7_11 : 48|8@1+ (1,0) [0|255] ""  PC
 SG_ M2P_DIAG_BYTE8_11 : 56|8@1+ (1,0) [0|255] ""  PC

BO_ 2416045724 M2P_DIAG__12: 8 MBMU
 SG_ M2P_DIAG_BYTE1_12 : 0|8@1+ (1,0) [0|255] ""  PC
 SG_ M2P_DIAG_BYTE2_12 : 8|8@1+ (1,0) [0|255] ""  PC
 SG_ M2P_DIAG_BYTE3_12 : 16|8@1+ (1,0) [0|255] ""  PC
 SG_ M2P_DIAG_BYTE4_12 : 24|8@1+ (1,0) [0|255] ""  PC
 SG_ M2P_DIAG_BYTE5_12 : 32|8@1+ (1,0) [0|255] ""  PC
 SG_ M2P_DIAG_BYTE6_12 : 40|8@1+ (1,0) [0|255] ""  PC
 SG_ M2P_DIAG_BYTE7_12 : 48|8@1+ (1,0) [0|255] ""  PC
 SG_ M2P_DIAG_BYTE8_12 : 56|8@1+ (1,0) [0|255] ""  PC

BO_ 2416045725 M2P_DIAG__13: 8 MBMU
 SG_ M2P_DIAG_BYTE1_13 : 0|8@1+ (1,0) [0|255] ""  PC
 SG_ M2P_DIAG_BYTE2_13 : 8|8@1+ (1,0) [0|255] ""  PC
 SG_ M2P_DIAG_BYTE3_13 : 16|8@1+ (1,0) [0|255] ""  PC
 SG_ M2P_DIAG_BYTE4_13 : 24|8@1+ (1,0) [0|255] ""  PC
 SG_ M2P_DIAG_BYTE5_13 : 32|8@1+ (1,0) [0|255] ""  PC
 SG_ M2P_DIAG_BYTE6_13 : 40|8@1+ (1,0) [0|255] ""  PC
 SG_ M2P_DIAG_BYTE7_13 : 48|8@1+ (1,0) [0|255] ""  PC
 SG_ M2P_DIAG_BYTE8_13 : 56|8@1+ (1,0) [0|255] ""  PC

BO_ 2416045726 M2P_DIAG__14: 8 MBMU
 SG_ M2P_DIAG_BYTE1_14 : 0|8@1+ (1,0) [0|255] ""  PC
 SG_ M2P_DIAG_BYTE2_14 : 8|8@1+ (1,0) [0|255] ""  PC
 SG_ M2P_DIAG_BYTE3_14 : 16|8@1+ (1,0) [0|255] ""  PC
 SG_ M2P_DIAG_BYTE4_14 : 24|8@1+ (1,0) [0|255] ""  PC
 SG_ M2P_DIAG_BYTE5_14 : 32|8@1+ (1,0) [0|255] ""  PC
 SG_ M2P_DIAG_BYTE6_14 : 40|8@1+ (1,0) [0|255] ""  PC
 SG_ M2P_DIAG_BYTE7_14 : 48|8@1+ (1,0) [0|255] ""  PC
 SG_ M2P_DIAG_BYTE8_14 : 56|8@1+ (1,0) [0|255] ""  PC

BO_ 2416045727 M2P_DIAG__15: 8 MBMU
 SG_ M2P_DIAG_BYTE1_15 : 0|8@1+ (1,0) [0|255] ""  PC
 SG_ M2P_DIAG_BYTE2_15 : 8|8@1+ (1,0) [0|255] ""  PC
 SG_ M2P_DIAG_BYTE3_15 : 16|8@1+ (1,0) [0|255] ""  PC
 SG_ M2P_DIAG_BYTE4_15 : 24|8@1+ (1,0) [0|255] ""  PC
 SG_ M2P_DIAG_BYTE5_15 : 32|8@1+ (1,0) [0|255] ""  PC
 SG_ M2P_DIAG_BYTE6_15 : 40|8@1+ (1,0) [0|255] ""  PC
 SG_ M2P_DIAG_BYTE7_15 : 48|8@1+ (1,0) [0|255] ""  PC
 SG_ M2P_DIAG_BYTE8_15 : 56|8@1+ (1,0) [0|255] ""  PC

BO_ 2416045728 M2P_DIAG__16: 8 MBMU
 SG_ M2P_DIAG_BYTE1_16 : 0|8@1+ (1,0) [0|255] ""  PC
 SG_ M2P_DIAG_BYTE2_16 : 8|8@1+ (1,0) [0|255] ""  PC
 SG_ M2P_DIAG_BYTE3_16 : 16|8@1+ (1,0) [0|255] ""  PC
 SG_ M2P_DIAG_BYTE4_16 : 24|8@1+ (1,0) [0|255] ""  PC
 SG_ M2P_DIAG_BYTE5_16 : 32|8@1+ (1,0) [0|255] ""  PC
 SG_ M2P_DIAG_BYTE6_16 : 40|8@1+ (1,0) [0|255] ""  PC
 SG_ M2P_DIAG_BYTE7_16 : 48|8@1+ (1,0) [0|255] ""  PC
 SG_ M2P_DIAG_BYTE8_16 : 56|8@1+ (1,0) [0|255] ""  PC

BO_ 2416045729 M2P_DIAG__17: 8 MBMU
 SG_ M2P_DIAG_BYTE1_17 : 0|8@1+ (1,0) [0|255] ""  PC
 SG_ M2P_DIAG_BYTE2_17 : 8|8@1+ (1,0) [0|255] ""  PC
 SG_ M2P_DIAG_BYTE3_17 : 16|8@1+ (1,0) [0|255] ""  PC
 SG_ M2P_DIAG_BYTE4_17 : 24|8@1+ (1,0) [0|255] ""  PC
 SG_ M2P_DIAG_BYTE5_17 : 32|8@1+ (1,0) [0|255] ""  PC
 SG_ M2P_DIAG_BYTE6_17 : 40|8@1+ (1,0) [0|255] ""  PC
 SG_ M2P_DIAG_BYTE7_17 : 48|8@1+ (1,0) [0|255] ""  PC
 SG_ M2P_DIAG_BYTE8_17 : 56|8@1+ (1,0) [0|255] ""  PC

BO_ 2416045730 M2P_DIAG__18: 8 MBMU
 SG_ M2P_DIAG_BYTE1_18 : 0|8@1+ (1,0) [0|255] ""  PC
 SG_ M2P_DIAG_BYTE2_18 : 8|8@1+ (1,0) [0|255] ""  PC
 SG_ M2P_DIAG_BYTE3_18 : 16|8@1+ (1,0) [0|255] ""  PC
 SG_ M2P_DIAG_BYTE4_18 : 24|8@1+ (1,0) [0|255] ""  PC
 SG_ M2P_DIAG_BYTE5_18 : 32|8@1+ (1,0) [0|255] ""  PC
 SG_ M2P_DIAG_BYTE6_18 : 40|8@1+ (1,0) [0|255] ""  PC
 SG_ M2P_DIAG_BYTE7_18 : 48|8@1+ (1,0) [0|255] ""  PC
 SG_ M2P_DIAG_BYTE8_18 : 56|8@1+ (1,0) [0|255] ""  PC

BO_ 2416045731 M2P_DIAG__19: 8 MBMU
 SG_ M2P_DIAG_BYTE1_19 : 0|8@1+ (1,0) [0|255] ""  PC
 SG_ M2P_DIAG_BYTE2_19 : 8|8@1+ (1,0) [0|255] ""  PC
 SG_ M2P_DIAG_BYTE3_19 : 16|8@1+ (1,0) [0|255] ""  PC
 SG_ M2P_DIAG_BYTE4_19 : 24|8@1+ (1,0) [0|255] ""  PC
 SG_ M2P_DIAG_BYTE5_19 : 32|8@1+ (1,0) [0|255] ""  PC
 SG_ M2P_DIAG_BYTE6_19 : 40|8@1+ (1,0) [0|255] ""  PC
 SG_ M2P_DIAG_BYTE7_19 : 48|8@1+ (1,0) [0|255] ""  PC
 SG_ M2P_DIAG_BYTE8_19 : 56|8@1+ (1,0) [0|255] ""  PC

BO_ 2416045732 M2P_DIAG__20: 8 MBMU
 SG_ M2P_DIAG_BYTE1_20 : 0|8@1+ (1,0) [0|255] ""  PC
 SG_ M2P_DIAG_BYTE2_20 : 8|8@1+ (1,0) [0|255] ""  PC
 SG_ M2P_DIAG_BYTE3_20 : 16|8@1+ (1,0) [0|255] ""  PC
 SG_ M2P_DIAG_BYTE4_20 : 24|8@1+ (1,0) [0|255] ""  PC
 SG_ M2P_DIAG_BYTE5_20 : 32|8@1+ (1,0) [0|255] ""  PC
 SG_ M2P_DIAG_BYTE6_20 : 40|8@1+ (1,0) [0|255] ""  PC
 SG_ M2P_DIAG_BYTE7_20 : 48|8@1+ (1,0) [0|255] ""  PC
 SG_ M2P_DIAG_BYTE8_20 : 56|8@1+ (1,0) [0|255] ""  PC

BO_ 2416045733 M2P_DIAG__21: 8 MBMU
 SG_ M2P_DIAG_BYTE1_21 : 0|8@1+ (1,0) [0|255] ""  PC
 SG_ M2P_DIAG_BYTE2_21 : 8|8@1+ (1,0) [0|255] ""  PC
 SG_ M2P_DIAG_BYTE3_21 : 16|8@1+ (1,0) [0|255] ""  PC
 SG_ M2P_DIAG_BYTE4_21 : 24|8@1+ (1,0) [0|255] ""  PC
 SG_ M2P_DIAG_BYTE5_21 : 32|8@1+ (1,0) [0|255] ""  PC
 SG_ M2P_DIAG_BYTE6_21 : 40|8@1+ (1,0) [0|255] ""  PC
 SG_ M2P_DIAG_BYTE7_21 : 48|8@1+ (1,0) [0|255] ""  PC
 SG_ M2P_DIAG_BYTE8_21 : 56|8@1+ (1,0) [0|255] ""  PC

BO_ 2416045734 M2P_DIAG__22: 8 MBMU
 SG_ M2P_DIAG_BYTE1_22 : 0|8@1+ (1,0) [0|255] ""  PC
 SG_ M2P_DIAG_BYTE2_22 : 8|8@1+ (1,0) [0|255] ""  PC
 SG_ M2P_DIAG_BYTE3_22 : 16|8@1+ (1,0) [0|255] ""  PC
 SG_ M2P_DIAG_BYTE4_22 : 24|8@1+ (1,0) [0|255] ""  PC
 SG_ M2P_DIAG_BYTE5_22 : 32|8@1+ (1,0) [0|255] ""  PC
 SG_ M2P_DIAG_BYTE6_22 : 40|8@1+ (1,0) [0|255] ""  PC
 SG_ M2P_DIAG_BYTE7_22 : 48|8@1+ (1,0) [0|255] ""  PC
 SG_ M2P_DIAG_BYTE8_22 : 56|8@1+ (1,0) [0|255] ""  PC

BO_ 2416045735 M2P_DIAG__23: 8 MBMU
 SG_ M2P_DIAG_BYTE1_23 : 0|8@1+ (1,0) [0|255] ""  PC
 SG_ M2P_DIAG_BYTE2_23 : 8|8@1+ (1,0) [0|255] ""  PC
 SG_ M2P_DIAG_BYTE3_23 : 16|8@1+ (1,0) [0|255] ""  PC
 SG_ M2P_DIAG_BYTE4_23 : 24|8@1+ (1,0) [0|255] ""  PC
 SG_ M2P_DIAG_BYTE5_23 : 32|8@1+ (1,0) [0|255] ""  PC
 SG_ M2P_DIAG_BYTE6_23 : 40|8@1+ (1,0) [0|255] ""  PC
 SG_ M2P_DIAG_BYTE7_23 : 48|8@1+ (1,0) [0|255] ""  PC
 SG_ M2P_DIAG_BYTE8_23 : 56|8@1+ (1,0) [0|255] ""  PC

BO_ 2416045736 M2P_DIAG__24: 8 MBMU
 SG_ M2P_DIAG_BYTE1_24 : 0|8@1+ (1,0) [0|255] ""  PC
 SG_ M2P_DIAG_BYTE2_24 : 8|8@1+ (1,0) [0|255] ""  PC
 SG_ M2P_DIAG_BYTE3_24 : 16|8@1+ (1,0) [0|255] ""  PC
 SG_ M2P_DIAG_BYTE4_24 : 24|8@1+ (1,0) [0|255] ""  PC
 SG_ M2P_DIAG_BYTE5_24 : 32|8@1+ (1,0) [0|255] ""  PC
 SG_ M2P_DIAG_BYTE6_24 : 40|8@1+ (1,0) [0|255] ""  PC
 SG_ M2P_DIAG_BYTE7_24 : 48|8@1+ (1,0) [0|255] ""  PC
 SG_ M2P_DIAG_BYTE8_24 : 56|8@1+ (1,0) [0|255] ""  PC

BO_ 2416045737 M2P_DIAG__25: 8 MBMU
 SG_ M2P_DIAG_BYTE1_25 : 0|8@1+ (1,0) [0|255] ""  PC
 SG_ M2P_DIAG_BYTE2_25 : 8|8@1+ (1,0) [0|255] ""  PC
 SG_ M2P_DIAG_BYTE3_25 : 16|8@1+ (1,0) [0|255] ""  PC
 SG_ M2P_DIAG_BYTE4_25 : 24|8@1+ (1,0) [0|255] ""  PC
 SG_ M2P_DIAG_BYTE5_25 : 32|8@1+ (1,0) [0|255] ""  PC
 SG_ M2P_DIAG_BYTE6_25 : 40|8@1+ (1,0) [0|255] ""  PC
 SG_ M2P_DIAG_BYTE7_25 : 48|8@1+ (1,0) [0|255] ""  PC
 SG_ M2P_DIAG_BYTE8_25 : 56|8@1+ (1,0) [0|255] ""  PC

BO_ 2416045738 M2P_DIAG__26: 8 MBMU
 SG_ M2P_DIAG_BYTE1_26 : 0|8@1+ (1,0) [0|255] ""  PC
 SG_ M2P_DIAG_BYTE2_26 : 8|8@1+ (1,0) [0|255] ""  PC
 SG_ M2P_DIAG_BYTE3_26 : 16|8@1+ (1,0) [0|255] ""  PC
 SG_ M2P_DIAG_BYTE4_26 : 24|8@1+ (1,0) [0|255] ""  PC
 SG_ M2P_DIAG_BYTE5_26 : 32|8@1+ (1,0) [0|255] ""  PC
 SG_ M2P_DIAG_BYTE6_26 : 40|8@1+ (1,0) [0|255] ""  PC
 SG_ M2P_DIAG_BYTE7_26 : 48|8@1+ (1,0) [0|255] ""  PC
 SG_ M2P_DIAG_BYTE8_26 : 56|8@1+ (1,0) [0|255] ""  PC

BO_ 2416045739 M2P_DIAG__27: 8 MBMU
 SG_ M2P_DIAG_BYTE1_27 : 0|8@1+ (1,0) [0|255] ""  PC
 SG_ M2P_DIAG_BYTE2_27 : 8|8@1+ (1,0) [0|255] ""  PC
 SG_ M2P_DIAG_BYTE3_27 : 16|8@1+ (1,0) [0|255] ""  PC
 SG_ M2P_DIAG_BYTE4_27 : 24|8@1+ (1,0) [0|255] ""  PC
 SG_ M2P_DIAG_BYTE5_27 : 32|8@1+ (1,0) [0|255] ""  PC
 SG_ M2P_DIAG_BYTE6_27 : 40|8@1+ (1,0) [0|255] ""  PC
 SG_ M2P_DIAG_BYTE7_27 : 48|8@1+ (1,0) [0|255] ""  PC
 SG_ M2P_DIAG_BYTE8_27 : 56|8@1+ (1,0) [0|255] ""  PC

BO_ 2416045740 M2P_DIAG__28: 8 MBMU
 SG_ M2P_DIAG_BYTE1_28 : 0|8@1+ (1,0) [0|255] ""  PC
 SG_ M2P_DIAG_BYTE2_28 : 8|8@1+ (1,0) [0|255] ""  PC
 SG_ M2P_DIAG_BYTE3_28 : 16|8@1+ (1,0) [0|255] ""  PC
 SG_ M2P_DIAG_BYTE4_28 : 24|8@1+ (1,0) [0|255] ""  PC
 SG_ M2P_DIAG_BYTE5_28 : 32|8@1+ (1,0) [0|255] ""  PC
 SG_ M2P_DIAG_BYTE6_28 : 40|8@1+ (1,0) [0|255] ""  PC
 SG_ M2P_DIAG_BYTE7_28 : 48|8@1+ (1,0) [0|255] ""  PC
 SG_ M2P_DIAG_BYTE8_28 : 56|8@1+ (1,0) [0|255] ""  PC

BO_ 2416045741 M2P_DIAG__29: 8 MBMU
 SG_ M2P_DIAG_BYTE1_29 : 0|8@1+ (1,0) [0|255] ""  PC
 SG_ M2P_DIAG_BYTE2_29 : 8|8@1+ (1,0) [0|255] ""  PC
 SG_ M2P_DIAG_BYTE3_29 : 16|8@1+ (1,0) [0|255] ""  PC
 SG_ M2P_DIAG_BYTE4_29 : 24|8@1+ (1,0) [0|255] ""  PC
 SG_ M2P_DIAG_BYTE5_29 : 32|8@1+ (1,0) [0|255] ""  PC
 SG_ M2P_DIAG_BYTE6_29 : 40|8@1+ (1,0) [0|255] ""  PC
 SG_ M2P_DIAG_BYTE7_29 : 48|8@1+ (1,0) [0|255] ""  PC
 SG_ M2P_DIAG_BYTE8_29 : 56|8@1+ (1,0) [0|255] ""  PC

BO_ 2416045742 M2P_DIAG__30: 8 MBMU
 SG_ M2P_DIAG_BYTE1_30 : 0|8@1+ (1,0) [0|255] ""  PC
 SG_ M2P_DIAG_BYTE2_30 : 8|8@1+ (1,0) [0|255] ""  PC
 SG_ M2P_DIAG_BYTE3_30 : 16|8@1+ (1,0) [0|255] ""  PC
 SG_ M2P_DIAG_BYTE4_30 : 24|8@1+ (1,0) [0|255] ""  PC
 SG_ M2P_DIAG_BYTE5_30 : 32|8@1+ (1,0) [0|255] ""  PC
 SG_ M2P_DIAG_BYTE6_30 : 40|8@1+ (1,0) [0|255] ""  PC
 SG_ M2P_DIAG_BYTE7_30 : 48|8@1+ (1,0) [0|255] ""  PC
 SG_ M2P_DIAG_BYTE8_30 : 56|8@1+ (1,0) [0|255] ""  PC

BO_ 2416045743 M2P_DIAG__31: 8 MBMU
 SG_ M2P_DIAG_BYTE1_31 : 0|8@1+ (1,0) [0|255] ""  PC
 SG_ M2P_DIAG_BYTE2_31 : 8|8@1+ (1,0) [0|255] ""  PC
 SG_ M2P_DIAG_BYTE3_31 : 16|8@1+ (1,0) [0|255] ""  PC
 SG_ M2P_DIAG_BYTE4_31 : 24|8@1+ (1,0) [0|255] ""  PC
 SG_ M2P_DIAG_BYTE5_31 : 32|8@1+ (1,0) [0|255] ""  PC
 SG_ M2P_DIAG_BYTE6_31 : 40|8@1+ (1,0) [0|255] ""  PC
 SG_ M2P_DIAG_BYTE7_31 : 48|8@1+ (1,0) [0|255] ""  PC
 SG_ M2P_DIAG_BYTE8_31 : 56|8@1+ (1,0) [0|255] ""  PC

BO_ 2416111249 M2P_Cfg1__01: 8 MBMU
 SG_ M2P_Cfg1_SW_Ver_Byte1_01 : 0|8@1+ (1,0) [0|255] ""  PC
 SG_ M2P_Cfg1_SW_Ver_Byte2_01 : 8|8@1+ (1,0) [0|255] ""  PC
 SG_ M2P_Cfg1_SW_Ver_Byte3_01 : 16|8@1+ (1,0) [0|255] ""  PC
 SG_ M2P_Cfg1_SW_Ver_Byte4_01 : 24|8@1+ (1,0) [0|255] ""  PC
 SG_ M2P_Cfg1_SW_Ver_Byte5_01 : 32|8@1+ (1,0) [0|255] ""  PC
 SG_ M2P_Cfg1_SW_Ver_Byte6_01 : 40|8@1+ (1,0) [0|255] ""  PC
 SG_ M2P_Cfg1_SW_Ver_Byte7_01 : 48|8@1+ (1,0) [0|255] ""  PC
 SG_ M2P_Cfg1_SW_Ver_Byte8_01 : 56|8@1+ (1,0) [0|255] ""  PC

BO_ 2416111250 M2P_Cfg1__02: 8 MBMU
 SG_ M2P_Cfg1_SW_Ver_Byte1_02 : 0|8@1+ (1,0) [0|255] ""  PC
 SG_ M2P_Cfg1_SW_Ver_Byte2_02 : 8|8@1+ (1,0) [0|255] ""  PC
 SG_ M2P_Cfg1_SW_Ver_Byte3_02 : 16|8@1+ (1,0) [0|255] ""  PC
 SG_ M2P_Cfg1_SW_Ver_Byte4_02 : 24|8@1+ (1,0) [0|255] ""  PC
 SG_ M2P_Cfg1_SW_Ver_Byte5_02 : 32|8@1+ (1,0) [0|255] ""  PC
 SG_ M2P_Cfg1_SW_Ver_Byte6_02 : 40|8@1+ (1,0) [0|255] ""  PC
 SG_ M2P_Cfg1_SW_Ver_Byte7_02 : 48|8@1+ (1,0) [0|255] ""  PC
 SG_ M2P_Cfg1_SW_Ver_Byte8_02 : 56|8@1+ (1,0) [0|255] ""  PC

BO_ 2416111251 M2P_Cfg1__03: 8 MBMU
 SG_ M2P_Cfg1_SW_Ver_Byte1_03 : 0|8@1+ (1,0) [0|255] ""  PC
 SG_ M2P_Cfg1_SW_Ver_Byte2_03 : 8|8@1+ (1,0) [0|255] ""  PC
 SG_ M2P_Cfg1_SW_Ver_Byte3_03 : 16|8@1+ (1,0) [0|255] ""  PC
 SG_ M2P_Cfg1_SW_Ver_Byte4_03 : 24|8@1+ (1,0) [0|255] ""  PC
 SG_ M2P_Cfg1_SW_Ver_Byte5_03 : 32|8@1+ (1,0) [0|255] ""  PC
 SG_ M2P_Cfg1_SW_Ver_Byte6_03 : 40|8@1+ (1,0) [0|255] ""  PC
 SG_ M2P_Cfg1_SW_Ver_Byte7_03 : 48|8@1+ (1,0) [0|255] ""  PC
 SG_ M2P_Cfg1_SW_Ver_Byte8_03 : 56|8@1+ (1,0) [0|255] ""  PC

BO_ 2416111252 M2P_Cfg1__04: 8 MBMU
 SG_ M2P_Cfg1_SW_Ver_Byte1_04 : 0|8@1+ (1,0) [0|255] ""  PC
 SG_ M2P_Cfg1_SW_Ver_Byte2_04 : 8|8@1+ (1,0) [0|255] ""  PC
 SG_ M2P_Cfg1_SW_Ver_Byte3_04 : 16|8@1+ (1,0) [0|255] ""  PC
 SG_ M2P_Cfg1_SW_Ver_Byte4_04 : 24|8@1+ (1,0) [0|255] ""  PC
 SG_ M2P_Cfg1_SW_Ver_Byte5_04 : 32|8@1+ (1,0) [0|255] ""  PC
 SG_ M2P_Cfg1_SW_Ver_Byte6_04 : 40|8@1+ (1,0) [0|255] ""  PC
 SG_ M2P_Cfg1_SW_Ver_Byte7_04 : 48|8@1+ (1,0) [0|255] ""  PC
 SG_ M2P_Cfg1_SW_Ver_Byte8_04 : 56|8@1+ (1,0) [0|255] ""  PC

BO_ 2416111253 M2P_Cfg1__05: 8 MBMU
 SG_ M2P_Cfg1_SW_Ver_Byte1_05 : 0|8@1+ (1,0) [0|255] ""  PC
 SG_ M2P_Cfg1_SW_Ver_Byte2_05 : 8|8@1+ (1,0) [0|255] ""  PC
 SG_ M2P_Cfg1_SW_Ver_Byte3_05 : 16|8@1+ (1,0) [0|255] ""  PC
 SG_ M2P_Cfg1_SW_Ver_Byte4_05 : 24|8@1+ (1,0) [0|255] ""  PC
 SG_ M2P_Cfg1_SW_Ver_Byte5_05 : 32|8@1+ (1,0) [0|255] ""  PC
 SG_ M2P_Cfg1_SW_Ver_Byte6_05 : 40|8@1+ (1,0) [0|255] ""  PC
 SG_ M2P_Cfg1_SW_Ver_Byte7_05 : 48|8@1+ (1,0) [0|255] ""  PC
 SG_ M2P_Cfg1_SW_Ver_Byte8_05 : 56|8@1+ (1,0) [0|255] ""  PC

BO_ 2416111254 M2P_Cfg1__06: 8 MBMU
 SG_ M2P_Cfg1_SW_Ver_Byte1_06 : 0|8@1+ (1,0) [0|255] ""  PC
 SG_ M2P_Cfg1_SW_Ver_Byte2_06 : 8|8@1+ (1,0) [0|255] ""  PC
 SG_ M2P_Cfg1_SW_Ver_Byte3_06 : 16|8@1+ (1,0) [0|255] ""  PC
 SG_ M2P_Cfg1_SW_Ver_Byte4_06 : 24|8@1+ (1,0) [0|255] ""  PC
 SG_ M2P_Cfg1_SW_Ver_Byte5_06 : 32|8@1+ (1,0) [0|255] ""  PC
 SG_ M2P_Cfg1_SW_Ver_Byte6_06 : 40|8@1+ (1,0) [0|255] ""  PC
 SG_ M2P_Cfg1_SW_Ver_Byte7_06 : 48|8@1+ (1,0) [0|255] ""  PC
 SG_ M2P_Cfg1_SW_Ver_Byte8_06 : 56|8@1+ (1,0) [0|255] ""  PC

BO_ 2416111255 M2P_Cfg1__07: 8 MBMU
 SG_ M2P_Cfg1_SW_Ver_Byte1_07 : 0|8@1+ (1,0) [0|255] ""  PC
 SG_ M2P_Cfg1_SW_Ver_Byte2_07 : 8|8@1+ (1,0) [0|255] ""  PC
 SG_ M2P_Cfg1_SW_Ver_Byte3_07 : 16|8@1+ (1,0) [0|255] ""  PC
 SG_ M2P_Cfg1_SW_Ver_Byte4_07 : 24|8@1+ (1,0) [0|255] ""  PC
 SG_ M2P_Cfg1_SW_Ver_Byte5_07 : 32|8@1+ (1,0) [0|255] ""  PC
 SG_ M2P_Cfg1_SW_Ver_Byte6_07 : 40|8@1+ (1,0) [0|255] ""  PC
 SG_ M2P_Cfg1_SW_Ver_Byte7_07 : 48|8@1+ (1,0) [0|255] ""  PC
 SG_ M2P_Cfg1_SW_Ver_Byte8_07 : 56|8@1+ (1,0) [0|255] ""  PC

BO_ 2416111256 M2P_Cfg1__08: 8 MBMU
 SG_ M2P_Cfg1_SW_Ver_Byte1_08 : 0|8@1+ (1,0) [0|255] ""  PC
 SG_ M2P_Cfg1_SW_Ver_Byte2_08 : 8|8@1+ (1,0) [0|255] ""  PC
 SG_ M2P_Cfg1_SW_Ver_Byte3_08 : 16|8@1+ (1,0) [0|255] ""  PC
 SG_ M2P_Cfg1_SW_Ver_Byte4_08 : 24|8@1+ (1,0) [0|255] ""  PC
 SG_ M2P_Cfg1_SW_Ver_Byte5_08 : 32|8@1+ (1,0) [0|255] ""  PC
 SG_ M2P_Cfg1_SW_Ver_Byte6_08 : 40|8@1+ (1,0) [0|255] ""  PC
 SG_ M2P_Cfg1_SW_Ver_Byte7_08 : 48|8@1+ (1,0) [0|255] ""  PC
 SG_ M2P_Cfg1_SW_Ver_Byte8_08 : 56|8@1+ (1,0) [0|255] ""  PC

BO_ 2416111257 M2P_Cfg1__09: 8 MBMU
 SG_ M2P_Cfg1_SW_Ver_Byte1_09 : 0|8@1+ (1,0) [0|255] ""  PC
 SG_ M2P_Cfg1_SW_Ver_Byte2_09 : 8|8@1+ (1,0) [0|255] ""  PC
 SG_ M2P_Cfg1_SW_Ver_Byte3_09 : 16|8@1+ (1,0) [0|255] ""  PC
 SG_ M2P_Cfg1_SW_Ver_Byte4_09 : 24|8@1+ (1,0) [0|255] ""  PC
 SG_ M2P_Cfg1_SW_Ver_Byte5_09 : 32|8@1+ (1,0) [0|255] ""  PC
 SG_ M2P_Cfg1_SW_Ver_Byte6_09 : 40|8@1+ (1,0) [0|255] ""  PC
 SG_ M2P_Cfg1_SW_Ver_Byte7_09 : 48|8@1+ (1,0) [0|255] ""  PC
 SG_ M2P_Cfg1_SW_Ver_Byte8_09 : 56|8@1+ (1,0) [0|255] ""  PC

BO_ 2416111258 M2P_Cfg1__10: 8 MBMU
 SG_ M2P_Cfg1_SW_Ver_Byte1_10 : 0|8@1+ (1,0) [0|255] ""  PC
 SG_ M2P_Cfg1_SW_Ver_Byte2_10 : 8|8@1+ (1,0) [0|255] ""  PC
 SG_ M2P_Cfg1_SW_Ver_Byte3_10 : 16|8@1+ (1,0) [0|255] ""  PC
 SG_ M2P_Cfg1_SW_Ver_Byte4_10 : 24|8@1+ (1,0) [0|255] ""  PC
 SG_ M2P_Cfg1_SW_Ver_Byte5_10 : 32|8@1+ (1,0) [0|255] ""  PC
 SG_ M2P_Cfg1_SW_Ver_Byte6_10 : 40|8@1+ (1,0) [0|255] ""  PC
 SG_ M2P_Cfg1_SW_Ver_Byte7_10 : 48|8@1+ (1,0) [0|255] ""  PC
 SG_ M2P_Cfg1_SW_Ver_Byte8_10 : 56|8@1+ (1,0) [0|255] ""  PC

BO_ 2416111259 M2P_Cfg1__11: 8 MBMU
 SG_ M2P_Cfg1_SW_Ver_Byte1_11 : 0|8@1+ (1,0) [0|255] ""  PC
 SG_ M2P_Cfg1_SW_Ver_Byte2_11 : 8|8@1+ (1,0) [0|255] ""  PC
 SG_ M2P_Cfg1_SW_Ver_Byte3_11 : 16|8@1+ (1,0) [0|255] ""  PC
 SG_ M2P_Cfg1_SW_Ver_Byte4_11 : 24|8@1+ (1,0) [0|255] ""  PC
 SG_ M2P_Cfg1_SW_Ver_Byte5_11 : 32|8@1+ (1,0) [0|255] ""  PC
 SG_ M2P_Cfg1_SW_Ver_Byte6_11 : 40|8@1+ (1,0) [0|255] ""  PC
 SG_ M2P_Cfg1_SW_Ver_Byte7_11 : 48|8@1+ (1,0) [0|255] ""  PC
 SG_ M2P_Cfg1_SW_Ver_Byte8_11 : 56|8@1+ (1,0) [0|255] ""  PC

BO_ 2416111260 M2P_Cfg1__12: 8 MBMU
 SG_ M2P_Cfg1_SW_Ver_Byte1_12 : 0|8@1+ (1,0) [0|255] ""  PC
 SG_ M2P_Cfg1_SW_Ver_Byte2_12 : 8|8@1+ (1,0) [0|255] ""  PC
 SG_ M2P_Cfg1_SW_Ver_Byte3_12 : 16|8@1+ (1,0) [0|255] ""  PC
 SG_ M2P_Cfg1_SW_Ver_Byte4_12 : 24|8@1+ (1,0) [0|255] ""  PC
 SG_ M2P_Cfg1_SW_Ver_Byte5_12 : 32|8@1+ (1,0) [0|255] ""  PC
 SG_ M2P_Cfg1_SW_Ver_Byte6_12 : 40|8@1+ (1,0) [0|255] ""  PC
 SG_ M2P_Cfg1_SW_Ver_Byte7_12 : 48|8@1+ (1,0) [0|255] ""  PC
 SG_ M2P_Cfg1_SW_Ver_Byte8_12 : 56|8@1+ (1,0) [0|255] ""  PC

BO_ 2416111261 M2P_Cfg1__13: 8 MBMU
 SG_ M2P_Cfg1_SW_Ver_Byte1_13 : 0|8@1+ (1,0) [0|255] ""  PC
 SG_ M2P_Cfg1_SW_Ver_Byte2_13 : 8|8@1+ (1,0) [0|255] ""  PC
 SG_ M2P_Cfg1_SW_Ver_Byte3_13 : 16|8@1+ (1,0) [0|255] ""  PC
 SG_ M2P_Cfg1_SW_Ver_Byte4_13 : 24|8@1+ (1,0) [0|255] ""  PC
 SG_ M2P_Cfg1_SW_Ver_Byte5_13 : 32|8@1+ (1,0) [0|255] ""  PC
 SG_ M2P_Cfg1_SW_Ver_Byte6_13 : 40|8@1+ (1,0) [0|255] ""  PC
 SG_ M2P_Cfg1_SW_Ver_Byte7_13 : 48|8@1+ (1,0) [0|255] ""  PC
 SG_ M2P_Cfg1_SW_Ver_Byte8_13 : 56|8@1+ (1,0) [0|255] ""  PC

BO_ 2416111262 M2P_Cfg1__14: 8 MBMU
 SG_ M2P_Cfg1_SW_Ver_Byte1_14 : 0|8@1+ (1,0) [0|255] ""  PC
 SG_ M2P_Cfg1_SW_Ver_Byte2_14 : 8|8@1+ (1,0) [0|255] ""  PC
 SG_ M2P_Cfg1_SW_Ver_Byte3_14 : 16|8@1+ (1,0) [0|255] ""  PC
 SG_ M2P_Cfg1_SW_Ver_Byte4_14 : 24|8@1+ (1,0) [0|255] ""  PC
 SG_ M2P_Cfg1_SW_Ver_Byte5_14 : 32|8@1+ (1,0) [0|255] ""  PC
 SG_ M2P_Cfg1_SW_Ver_Byte6_14 : 40|8@1+ (1,0) [0|255] ""  PC
 SG_ M2P_Cfg1_SW_Ver_Byte7_14 : 48|8@1+ (1,0) [0|255] ""  PC
 SG_ M2P_Cfg1_SW_Ver_Byte8_14 : 56|8@1+ (1,0) [0|255] ""  PC

BO_ 2416111263 M2P_Cfg1__15: 8 MBMU
 SG_ M2P_Cfg1_SW_Ver_Byte1_15 : 0|8@1+ (1,0) [0|255] ""  PC
 SG_ M2P_Cfg1_SW_Ver_Byte2_15 : 8|8@1+ (1,0) [0|255] ""  PC
 SG_ M2P_Cfg1_SW_Ver_Byte3_15 : 16|8@1+ (1,0) [0|255] ""  PC
 SG_ M2P_Cfg1_SW_Ver_Byte4_15 : 24|8@1+ (1,0) [0|255] ""  PC
 SG_ M2P_Cfg1_SW_Ver_Byte5_15 : 32|8@1+ (1,0) [0|255] ""  PC
 SG_ M2P_Cfg1_SW_Ver_Byte6_15 : 40|8@1+ (1,0) [0|255] ""  PC
 SG_ M2P_Cfg1_SW_Ver_Byte7_15 : 48|8@1+ (1,0) [0|255] ""  PC
 SG_ M2P_Cfg1_SW_Ver_Byte8_15 : 56|8@1+ (1,0) [0|255] ""  PC

BO_ 2416111264 M2P_Cfg1__16: 8 MBMU
 SG_ M2P_Cfg1_SW_Ver_Byte1_16 : 0|8@1+ (1,0) [0|255] ""  PC
 SG_ M2P_Cfg1_SW_Ver_Byte2_16 : 8|8@1+ (1,0) [0|255] ""  PC
 SG_ M2P_Cfg1_SW_Ver_Byte3_16 : 16|8@1+ (1,0) [0|255] ""  PC
 SG_ M2P_Cfg1_SW_Ver_Byte4_16 : 24|8@1+ (1,0) [0|255] ""  PC
 SG_ M2P_Cfg1_SW_Ver_Byte5_16 : 32|8@1+ (1,0) [0|255] ""  PC
 SG_ M2P_Cfg1_SW_Ver_Byte6_16 : 40|8@1+ (1,0) [0|255] ""  PC
 SG_ M2P_Cfg1_SW_Ver_Byte7_16 : 48|8@1+ (1,0) [0|255] ""  PC
 SG_ M2P_Cfg1_SW_Ver_Byte8_16 : 56|8@1+ (1,0) [0|255] ""  PC

BO_ 2416111265 M2P_Cfg1__17: 8 MBMU
 SG_ M2P_Cfg1_SW_Ver_Byte1_17 : 0|8@1+ (1,0) [0|255] ""  PC
 SG_ M2P_Cfg1_SW_Ver_Byte2_17 : 8|8@1+ (1,0) [0|255] ""  PC
 SG_ M2P_Cfg1_SW_Ver_Byte3_17 : 16|8@1+ (1,0) [0|255] ""  PC
 SG_ M2P_Cfg1_SW_Ver_Byte4_17 : 24|8@1+ (1,0) [0|255] ""  PC
 SG_ M2P_Cfg1_SW_Ver_Byte5_17 : 32|8@1+ (1,0) [0|255] ""  PC
 SG_ M2P_Cfg1_SW_Ver_Byte6_17 : 40|8@1+ (1,0) [0|255] ""  PC
 SG_ M2P_Cfg1_SW_Ver_Byte7_17 : 48|8@1+ (1,0) [0|255] ""  PC
 SG_ M2P_Cfg1_SW_Ver_Byte8_17 : 56|8@1+ (1,0) [0|255] ""  PC

BO_ 2416111266 M2P_Cfg1__18: 8 MBMU
 SG_ M2P_Cfg1_SW_Ver_Byte1_18 : 0|8@1+ (1,0) [0|255] ""  PC
 SG_ M2P_Cfg1_SW_Ver_Byte2_18 : 8|8@1+ (1,0) [0|255] ""  PC
 SG_ M2P_Cfg1_SW_Ver_Byte3_18 : 16|8@1+ (1,0) [0|255] ""  PC
 SG_ M2P_Cfg1_SW_Ver_Byte4_18 : 24|8@1+ (1,0) [0|255] ""  PC
 SG_ M2P_Cfg1_SW_Ver_Byte5_18 : 32|8@1+ (1,0) [0|255] ""  PC
 SG_ M2P_Cfg1_SW_Ver_Byte6_18 : 40|8@1+ (1,0) [0|255] ""  PC
 SG_ M2P_Cfg1_SW_Ver_Byte7_18 : 48|8@1+ (1,0) [0|255] ""  PC
 SG_ M2P_Cfg1_SW_Ver_Byte8_18 : 56|8@1+ (1,0) [0|255] ""  PC

BO_ 2416111267 M2P_Cfg1__19: 8 MBMU
 SG_ M2P_Cfg1_SW_Ver_Byte1_19 : 0|8@1+ (1,0) [0|255] ""  PC
 SG_ M2P_Cfg1_SW_Ver_Byte2_19 : 8|8@1+ (1,0) [0|255] ""  PC
 SG_ M2P_Cfg1_SW_Ver_Byte3_19 : 16|8@1+ (1,0) [0|255] ""  PC
 SG_ M2P_Cfg1_SW_Ver_Byte4_19 : 24|8@1+ (1,0) [0|255] ""  PC
 SG_ M2P_Cfg1_SW_Ver_Byte5_19 : 32|8@1+ (1,0) [0|255] ""  PC
 SG_ M2P_Cfg1_SW_Ver_Byte6_19 : 40|8@1+ (1,0) [0|255] ""  PC
 SG_ M2P_Cfg1_SW_Ver_Byte7_19 : 48|8@1+ (1,0) [0|255] ""  PC
 SG_ M2P_Cfg1_SW_Ver_Byte8_19 : 56|8@1+ (1,0) [0|255] ""  PC

BO_ 2416111268 M2P_Cfg1__20: 8 MBMU
 SG_ M2P_Cfg1_SW_Ver_Byte1_20 : 0|8@1+ (1,0) [0|255] ""  PC
 SG_ M2P_Cfg1_SW_Ver_Byte2_20 : 8|8@1+ (1,0) [0|255] ""  PC
 SG_ M2P_Cfg1_SW_Ver_Byte3_20 : 16|8@1+ (1,0) [0|255] ""  PC
 SG_ M2P_Cfg1_SW_Ver_Byte4_20 : 24|8@1+ (1,0) [0|255] ""  PC
 SG_ M2P_Cfg1_SW_Ver_Byte5_20 : 32|8@1+ (1,0) [0|255] ""  PC
 SG_ M2P_Cfg1_SW_Ver_Byte6_20 : 40|8@1+ (1,0) [0|255] ""  PC
 SG_ M2P_Cfg1_SW_Ver_Byte7_20 : 48|8@1+ (1,0) [0|255] ""  PC
 SG_ M2P_Cfg1_SW_Ver_Byte8_20 : 56|8@1+ (1,0) [0|255] ""  PC

BO_ 2416111269 M2P_Cfg1__21: 8 MBMU
 SG_ M2P_Cfg1_SW_Ver_Byte1_21 : 0|8@1+ (1,0) [0|255] ""  PC
 SG_ M2P_Cfg1_SW_Ver_Byte2_21 : 8|8@1+ (1,0) [0|255] ""  PC
 SG_ M2P_Cfg1_SW_Ver_Byte3_21 : 16|8@1+ (1,0) [0|255] ""  PC
 SG_ M2P_Cfg1_SW_Ver_Byte4_21 : 24|8@1+ (1,0) [0|255] ""  PC
 SG_ M2P_Cfg1_SW_Ver_Byte5_21 : 32|8@1+ (1,0) [0|255] ""  PC
 SG_ M2P_Cfg1_SW_Ver_Byte6_21 : 40|8@1+ (1,0) [0|255] ""  PC
 SG_ M2P_Cfg1_SW_Ver_Byte7_21 : 48|8@1+ (1,0) [0|255] ""  PC
 SG_ M2P_Cfg1_SW_Ver_Byte8_21 : 56|8@1+ (1,0) [0|255] ""  PC

BO_ 2416111270 M2P_Cfg1__22: 8 MBMU
 SG_ M2P_Cfg1_SW_Ver_Byte1_22 : 0|8@1+ (1,0) [0|255] ""  PC
 SG_ M2P_Cfg1_SW_Ver_Byte2_22 : 8|8@1+ (1,0) [0|255] ""  PC
 SG_ M2P_Cfg1_SW_Ver_Byte3_22 : 16|8@1+ (1,0) [0|255] ""  PC
 SG_ M2P_Cfg1_SW_Ver_Byte4_22 : 24|8@1+ (1,0) [0|255] ""  PC
 SG_ M2P_Cfg1_SW_Ver_Byte5_22 : 32|8@1+ (1,0) [0|255] ""  PC
 SG_ M2P_Cfg1_SW_Ver_Byte6_22 : 40|8@1+ (1,0) [0|255] ""  PC
 SG_ M2P_Cfg1_SW_Ver_Byte7_22 : 48|8@1+ (1,0) [0|255] ""  PC
 SG_ M2P_Cfg1_SW_Ver_Byte8_22 : 56|8@1+ (1,0) [0|255] ""  PC

BO_ 2416111271 M2P_Cfg1__23: 8 MBMU
 SG_ M2P_Cfg1_SW_Ver_Byte1_23 : 0|8@1+ (1,0) [0|255] ""  PC
 SG_ M2P_Cfg1_SW_Ver_Byte2_23 : 8|8@1+ (1,0) [0|255] ""  PC
 SG_ M2P_Cfg1_SW_Ver_Byte3_23 : 16|8@1+ (1,0) [0|255] ""  PC
 SG_ M2P_Cfg1_SW_Ver_Byte4_23 : 24|8@1+ (1,0) [0|255] ""  PC
 SG_ M2P_Cfg1_SW_Ver_Byte5_23 : 32|8@1+ (1,0) [0|255] ""  PC
 SG_ M2P_Cfg1_SW_Ver_Byte6_23 : 40|8@1+ (1,0) [0|255] ""  PC
 SG_ M2P_Cfg1_SW_Ver_Byte7_23 : 48|8@1+ (1,0) [0|255] ""  PC
 SG_ M2P_Cfg1_SW_Ver_Byte8_23 : 56|8@1+ (1,0) [0|255] ""  PC

BO_ 2416111272 M2P_Cfg1__24: 8 MBMU
 SG_ M2P_Cfg1_SW_Ver_Byte1_24 : 0|8@1+ (1,0) [0|255] ""  PC
 SG_ M2P_Cfg1_SW_Ver_Byte2_24 : 8|8@1+ (1,0) [0|255] ""  PC
 SG_ M2P_Cfg1_SW_Ver_Byte3_24 : 16|8@1+ (1,0) [0|255] ""  PC
 SG_ M2P_Cfg1_SW_Ver_Byte4_24 : 24|8@1+ (1,0) [0|255] ""  PC
 SG_ M2P_Cfg1_SW_Ver_Byte5_24 : 32|8@1+ (1,0) [0|255] ""  PC
 SG_ M2P_Cfg1_SW_Ver_Byte6_24 : 40|8@1+ (1,0) [0|255] ""  PC
 SG_ M2P_Cfg1_SW_Ver_Byte7_24 : 48|8@1+ (1,0) [0|255] ""  PC
 SG_ M2P_Cfg1_SW_Ver_Byte8_24 : 56|8@1+ (1,0) [0|255] ""  PC

BO_ 2416111273 M2P_Cfg1__25: 8 MBMU
 SG_ M2P_Cfg1_SW_Ver_Byte1_25 : 0|8@1+ (1,0) [0|255] ""  PC
 SG_ M2P_Cfg1_SW_Ver_Byte2_25 : 8|8@1+ (1,0) [0|255] ""  PC
 SG_ M2P_Cfg1_SW_Ver_Byte3_25 : 16|8@1+ (1,0) [0|255] ""  PC
 SG_ M2P_Cfg1_SW_Ver_Byte4_25 : 24|8@1+ (1,0) [0|255] ""  PC
 SG_ M2P_Cfg1_SW_Ver_Byte5_25 : 32|8@1+ (1,0) [0|255] ""  PC
 SG_ M2P_Cfg1_SW_Ver_Byte6_25 : 40|8@1+ (1,0) [0|255] ""  PC
 SG_ M2P_Cfg1_SW_Ver_Byte7_25 : 48|8@1+ (1,0) [0|255] ""  PC
 SG_ M2P_Cfg1_SW_Ver_Byte8_25 : 56|8@1+ (1,0) [0|255] ""  PC

BO_ 2416111274 M2P_Cfg1__26: 8 MBMU
 SG_ M2P_Cfg1_SW_Ver_Byte1_26 : 0|8@1+ (1,0) [0|255] ""  PC
 SG_ M2P_Cfg1_SW_Ver_Byte2_26 : 8|8@1+ (1,0) [0|255] ""  PC
 SG_ M2P_Cfg1_SW_Ver_Byte3_26 : 16|8@1+ (1,0) [0|255] ""  PC
 SG_ M2P_Cfg1_SW_Ver_Byte4_26 : 24|8@1+ (1,0) [0|255] ""  PC
 SG_ M2P_Cfg1_SW_Ver_Byte5_26 : 32|8@1+ (1,0) [0|255] ""  PC
 SG_ M2P_Cfg1_SW_Ver_Byte6_26 : 40|8@1+ (1,0) [0|255] ""  PC
 SG_ M2P_Cfg1_SW_Ver_Byte7_26 : 48|8@1+ (1,0) [0|255] ""  PC
 SG_ M2P_Cfg1_SW_Ver_Byte8_26 : 56|8@1+ (1,0) [0|255] ""  PC

BO_ 2416111275 M2P_Cfg1__27: 8 MBMU
 SG_ M2P_Cfg1_SW_Ver_Byte1_27 : 0|8@1+ (1,0) [0|255] ""  PC
 SG_ M2P_Cfg1_SW_Ver_Byte2_27 : 8|8@1+ (1,0) [0|255] ""  PC
 SG_ M2P_Cfg1_SW_Ver_Byte3_27 : 16|8@1+ (1,0) [0|255] ""  PC
 SG_ M2P_Cfg1_SW_Ver_Byte4_27 : 24|8@1+ (1,0) [0|255] ""  PC
 SG_ M2P_Cfg1_SW_Ver_Byte5_27 : 32|8@1+ (1,0) [0|255] ""  PC
 SG_ M2P_Cfg1_SW_Ver_Byte6_27 : 40|8@1+ (1,0) [0|255] ""  PC
 SG_ M2P_Cfg1_SW_Ver_Byte7_27 : 48|8@1+ (1,0) [0|255] ""  PC
 SG_ M2P_Cfg1_SW_Ver_Byte8_27 : 56|8@1+ (1,0) [0|255] ""  PC

BO_ 2416111276 M2P_Cfg1__28: 8 MBMU
 SG_ M2P_Cfg1_SW_Ver_Byte1_28 : 0|8@1+ (1,0) [0|255] ""  PC
 SG_ M2P_Cfg1_SW_Ver_Byte2_28 : 8|8@1+ (1,0) [0|255] ""  PC
 SG_ M2P_Cfg1_SW_Ver_Byte3_28 : 16|8@1+ (1,0) [0|255] ""  PC
 SG_ M2P_Cfg1_SW_Ver_Byte4_28 : 24|8@1+ (1,0) [0|255] ""  PC
 SG_ M2P_Cfg1_SW_Ver_Byte5_28 : 32|8@1+ (1,0) [0|255] ""  PC
 SG_ M2P_Cfg1_SW_Ver_Byte6_28 : 40|8@1+ (1,0) [0|255] ""  PC
 SG_ M2P_Cfg1_SW_Ver_Byte7_28 : 48|8@1+ (1,0) [0|255] ""  PC
 SG_ M2P_Cfg1_SW_Ver_Byte8_28 : 56|8@1+ (1,0) [0|255] ""  PC

BO_ 2416111277 M2P_Cfg1__29: 8 MBMU
 SG_ M2P_Cfg1_SW_Ver_Byte1_29 : 0|8@1+ (1,0) [0|255] ""  PC
 SG_ M2P_Cfg1_SW_Ver_Byte2_29 : 8|8@1+ (1,0) [0|255] ""  PC
 SG_ M2P_Cfg1_SW_Ver_Byte3_29 : 16|8@1+ (1,0) [0|255] ""  PC
 SG_ M2P_Cfg1_SW_Ver_Byte4_29 : 24|8@1+ (1,0) [0|255] ""  PC
 SG_ M2P_Cfg1_SW_Ver_Byte5_29 : 32|8@1+ (1,0) [0|255] ""  PC
 SG_ M2P_Cfg1_SW_Ver_Byte6_29 : 40|8@1+ (1,0) [0|255] ""  PC
 SG_ M2P_Cfg1_SW_Ver_Byte7_29 : 48|8@1+ (1,0) [0|255] ""  PC
 SG_ M2P_Cfg1_SW_Ver_Byte8_29 : 56|8@1+ (1,0) [0|255] ""  PC

BO_ 2416111278 M2P_Cfg1__30: 8 MBMU
 SG_ M2P_Cfg1_SW_Ver_Byte1_30 : 0|8@1+ (1,0) [0|255] ""  PC
 SG_ M2P_Cfg1_SW_Ver_Byte2_30 : 8|8@1+ (1,0) [0|255] ""  PC
 SG_ M2P_Cfg1_SW_Ver_Byte3_30 : 16|8@1+ (1,0) [0|255] ""  PC
 SG_ M2P_Cfg1_SW_Ver_Byte4_30 : 24|8@1+ (1,0) [0|255] ""  PC
 SG_ M2P_Cfg1_SW_Ver_Byte5_30 : 32|8@1+ (1,0) [0|255] ""  PC
 SG_ M2P_Cfg1_SW_Ver_Byte6_30 : 40|8@1+ (1,0) [0|255] ""  PC
 SG_ M2P_Cfg1_SW_Ver_Byte7_30 : 48|8@1+ (1,0) [0|255] ""  PC
 SG_ M2P_Cfg1_SW_Ver_Byte8_30 : 56|8@1+ (1,0) [0|255] ""  PC

BO_ 2416111279 M2P_Cfg1__31: 8 MBMU
 SG_ M2P_Cfg1_SW_Ver_Byte1_31 : 0|8@1+ (1,0) [0|255] ""  PC
 SG_ M2P_Cfg1_SW_Ver_Byte2_31 : 8|8@1+ (1,0) [0|255] ""  PC
 SG_ M2P_Cfg1_SW_Ver_Byte3_31 : 16|8@1+ (1,0) [0|255] ""  PC
 SG_ M2P_Cfg1_SW_Ver_Byte4_31 : 24|8@1+ (1,0) [0|255] ""  PC
 SG_ M2P_Cfg1_SW_Ver_Byte5_31 : 32|8@1+ (1,0) [0|255] ""  PC
 SG_ M2P_Cfg1_SW_Ver_Byte6_31 : 40|8@1+ (1,0) [0|255] ""  PC
 SG_ M2P_Cfg1_SW_Ver_Byte7_31 : 48|8@1+ (1,0) [0|255] ""  PC
 SG_ M2P_Cfg1_SW_Ver_Byte8_31 : 56|8@1+ (1,0) [0|255] ""  PC

BO_ 2416176785 M2P_Cfg2__01: 8 MBMU
 SG_ M2P_Cfg2_SW_Ver_Byte9_01 : 0|8@1+ (1,0) [0|255] ""  PC
 SG_ M2P_Cfg2_SW_Ver_Byte10_01 : 8|8@1+ (1,0) [0|255] ""  PC
 SG_ M2P_Cfg2_SW_Ver_Byte11_01 : 16|8@1+ (1,0) [0|255] ""  PC
 SG_ M2P_Cfg2_SW_Ver_Byte12_01 : 24|8@1+ (1,0) [0|255] ""  PC
 SG_ M2P_Cfg2_SW_Ver_Byte13_01 : 32|8@1+ (1,0) [0|255] ""  PC
 SG_ M2P_Cfg2_SW_Ver_Byte14_01 : 40|8@1+ (1,0) [0|255] ""  PC
 SG_ M2P_Cfg2_SW_Ver_Byte15_01 : 48|8@1+ (1,0) [0|255] ""  PC
 SG_ M2P_Cfg2_SW_Ver_Byte16_01 : 56|8@1+ (1,0) [0|255] ""  PC

BO_ 2416176786 M2P_Cfg2__02: 8 MBMU
 SG_ M2P_Cfg2_SW_Ver_Byte9_02 : 0|8@1+ (1,0) [0|255] ""  PC
 SG_ M2P_Cfg2_SW_Ver_Byte10_02 : 8|8@1+ (1,0) [0|255] ""  PC
 SG_ M2P_Cfg2_SW_Ver_Byte11_02 : 16|8@1+ (1,0) [0|255] ""  PC
 SG_ M2P_Cfg2_SW_Ver_Byte12_02 : 24|8@1+ (1,0) [0|255] ""  PC
 SG_ M2P_Cfg2_SW_Ver_Byte13_02 : 32|8@1+ (1,0) [0|255] ""  PC
 SG_ M2P_Cfg2_SW_Ver_Byte14_02 : 40|8@1+ (1,0) [0|255] ""  PC
 SG_ M2P_Cfg2_SW_Ver_Byte15_02 : 48|8@1+ (1,0) [0|255] ""  PC
 SG_ M2P_Cfg2_SW_Ver_Byte16_02 : 56|8@1+ (1,0) [0|255] ""  PC

BO_ 2416176787 M2P_Cfg2__03: 8 MBMU
 SG_ M2P_Cfg2_SW_Ver_Byte9_03 : 0|8@1+ (1,0) [0|255] ""  PC
 SG_ M2P_Cfg2_SW_Ver_Byte10_03 : 8|8@1+ (1,0) [0|255] ""  PC
 SG_ M2P_Cfg2_SW_Ver_Byte11_03 : 16|8@1+ (1,0) [0|255] ""  PC
 SG_ M2P_Cfg2_SW_Ver_Byte12_03 : 24|8@1+ (1,0) [0|255] ""  PC
 SG_ M2P_Cfg2_SW_Ver_Byte13_03 : 32|8@1+ (1,0) [0|255] ""  PC
 SG_ M2P_Cfg2_SW_Ver_Byte14_03 : 40|8@1+ (1,0) [0|255] ""  PC
 SG_ M2P_Cfg2_SW_Ver_Byte15_03 : 48|8@1+ (1,0) [0|255] ""  PC
 SG_ M2P_Cfg2_SW_Ver_Byte16_03 : 56|8@1+ (1,0) [0|255] ""  PC

BO_ 2416176788 M2P_Cfg2__04: 8 MBMU
 SG_ M2P_Cfg2_SW_Ver_Byte9_04 : 0|8@1+ (1,0) [0|255] ""  PC
 SG_ M2P_Cfg2_SW_Ver_Byte10_04 : 8|8@1+ (1,0) [0|255] ""  PC
 SG_ M2P_Cfg2_SW_Ver_Byte11_04 : 16|8@1+ (1,0) [0|255] ""  PC
 SG_ M2P_Cfg2_SW_Ver_Byte12_04 : 24|8@1+ (1,0) [0|255] ""  PC
 SG_ M2P_Cfg2_SW_Ver_Byte13_04 : 32|8@1+ (1,0) [0|255] ""  PC
 SG_ M2P_Cfg2_SW_Ver_Byte14_04 : 40|8@1+ (1,0) [0|255] ""  PC
 SG_ M2P_Cfg2_SW_Ver_Byte15_04 : 48|8@1+ (1,0) [0|255] ""  PC
 SG_ M2P_Cfg2_SW_Ver_Byte16_04 : 56|8@1+ (1,0) [0|255] ""  PC

BO_ 2416176789 M2P_Cfg2__05: 8 MBMU
 SG_ M2P_Cfg2_SW_Ver_Byte9_05 : 0|8@1+ (1,0) [0|255] ""  PC
 SG_ M2P_Cfg2_SW_Ver_Byte10_05 : 8|8@1+ (1,0) [0|255] ""  PC
 SG_ M2P_Cfg2_SW_Ver_Byte11_05 : 16|8@1+ (1,0) [0|255] ""  PC
 SG_ M2P_Cfg2_SW_Ver_Byte12_05 : 24|8@1+ (1,0) [0|255] ""  PC
 SG_ M2P_Cfg2_SW_Ver_Byte13_05 : 32|8@1+ (1,0) [0|255] ""  PC
 SG_ M2P_Cfg2_SW_Ver_Byte14_05 : 40|8@1+ (1,0) [0|255] ""  PC
 SG_ M2P_Cfg2_SW_Ver_Byte15_05 : 48|8@1+ (1,0) [0|255] ""  PC
 SG_ M2P_Cfg2_SW_Ver_Byte16_05 : 56|8@1+ (1,0) [0|255] ""  PC

BO_ 2416176790 M2P_Cfg2__06: 8 MBMU
 SG_ M2P_Cfg2_SW_Ver_Byte9_06 : 0|8@1+ (1,0) [0|255] ""  PC
 SG_ M2P_Cfg2_SW_Ver_Byte10_06 : 8|8@1+ (1,0) [0|255] ""  PC
 SG_ M2P_Cfg2_SW_Ver_Byte11_06 : 16|8@1+ (1,0) [0|255] ""  PC
 SG_ M2P_Cfg2_SW_Ver_Byte12_06 : 24|8@1+ (1,0) [0|255] ""  PC
 SG_ M2P_Cfg2_SW_Ver_Byte13_06 : 32|8@1+ (1,0) [0|255] ""  PC
 SG_ M2P_Cfg2_SW_Ver_Byte14_06 : 40|8@1+ (1,0) [0|255] ""  PC
 SG_ M2P_Cfg2_SW_Ver_Byte15_06 : 48|8@1+ (1,0) [0|255] ""  PC
 SG_ M2P_Cfg2_SW_Ver_Byte16_06 : 56|8@1+ (1,0) [0|255] ""  PC

BO_ 2416176791 M2P_Cfg2__07: 8 MBMU
 SG_ M2P_Cfg2_SW_Ver_Byte9_07 : 0|8@1+ (1,0) [0|255] ""  PC
 SG_ M2P_Cfg2_SW_Ver_Byte10_07 : 8|8@1+ (1,0) [0|255] ""  PC
 SG_ M2P_Cfg2_SW_Ver_Byte11_07 : 16|8@1+ (1,0) [0|255] ""  PC
 SG_ M2P_Cfg2_SW_Ver_Byte12_07 : 24|8@1+ (1,0) [0|255] ""  PC
 SG_ M2P_Cfg2_SW_Ver_Byte13_07 : 32|8@1+ (1,0) [0|255] ""  PC
 SG_ M2P_Cfg2_SW_Ver_Byte14_07 : 40|8@1+ (1,0) [0|255] ""  PC
 SG_ M2P_Cfg2_SW_Ver_Byte15_07 : 48|8@1+ (1,0) [0|255] ""  PC
 SG_ M2P_Cfg2_SW_Ver_Byte16_07 : 56|8@1+ (1,0) [0|255] ""  PC

BO_ 2416176792 M2P_Cfg2__08: 8 MBMU
 SG_ M2P_Cfg2_SW_Ver_Byte9_08 : 0|8@1+ (1,0) [0|255] ""  PC
 SG_ M2P_Cfg2_SW_Ver_Byte10_08 : 8|8@1+ (1,0) [0|255] ""  PC
 SG_ M2P_Cfg2_SW_Ver_Byte11_08 : 16|8@1+ (1,0) [0|255] ""  PC
 SG_ M2P_Cfg2_SW_Ver_Byte12_08 : 24|8@1+ (1,0) [0|255] ""  PC
 SG_ M2P_Cfg2_SW_Ver_Byte13_08 : 32|8@1+ (1,0) [0|255] ""  PC
 SG_ M2P_Cfg2_SW_Ver_Byte14_08 : 40|8@1+ (1,0) [0|255] ""  PC
 SG_ M2P_Cfg2_SW_Ver_Byte15_08 : 48|8@1+ (1,0) [0|255] ""  PC
 SG_ M2P_Cfg2_SW_Ver_Byte16_08 : 56|8@1+ (1,0) [0|255] ""  PC

BO_ 2416176793 M2P_Cfg2__09: 8 MBMU
 SG_ M2P_Cfg2_SW_Ver_Byte9_09 : 0|8@1+ (1,0) [0|255] ""  PC
 SG_ M2P_Cfg2_SW_Ver_Byte10_09 : 8|8@1+ (1,0) [0|255] ""  PC
 SG_ M2P_Cfg2_SW_Ver_Byte11_09 : 16|8@1+ (1,0) [0|255] ""  PC
 SG_ M2P_Cfg2_SW_Ver_Byte12_09 : 24|8@1+ (1,0) [0|255] ""  PC
 SG_ M2P_Cfg2_SW_Ver_Byte13_09 : 32|8@1+ (1,0) [0|255] ""  PC
 SG_ M2P_Cfg2_SW_Ver_Byte14_09 : 40|8@1+ (1,0) [0|255] ""  PC
 SG_ M2P_Cfg2_SW_Ver_Byte15_09 : 48|8@1+ (1,0) [0|255] ""  PC
 SG_ M2P_Cfg2_SW_Ver_Byte16_09 : 56|8@1+ (1,0) [0|255] ""  PC

BO_ 2416176794 M2P_Cfg2__10: 8 MBMU
 SG_ M2P_Cfg2_SW_Ver_Byte9_10 : 0|8@1+ (1,0) [0|255] ""  PC
 SG_ M2P_Cfg2_SW_Ver_Byte10_10 : 8|8@1+ (1,0) [0|255] ""  PC
 SG_ M2P_Cfg2_SW_Ver_Byte11_10 : 16|8@1+ (1,0) [0|255] ""  PC
 SG_ M2P_Cfg2_SW_Ver_Byte12_10 : 24|8@1+ (1,0) [0|255] ""  PC
 SG_ M2P_Cfg2_SW_Ver_Byte13_10 : 32|8@1+ (1,0) [0|255] ""  PC
 SG_ M2P_Cfg2_SW_Ver_Byte14_10 : 40|8@1+ (1,0) [0|255] ""  PC
 SG_ M2P_Cfg2_SW_Ver_Byte15_10 : 48|8@1+ (1,0) [0|255] ""  PC
 SG_ M2P_Cfg2_SW_Ver_Byte16_10 : 56|8@1+ (1,0) [0|255] ""  PC

BO_ 2416176795 M2P_Cfg2__11: 8 MBMU
 SG_ M2P_Cfg2_SW_Ver_Byte9_11 : 0|8@1+ (1,0) [0|255] ""  PC
 SG_ M2P_Cfg2_SW_Ver_Byte10_11 : 8|8@1+ (1,0) [0|255] ""  PC
 SG_ M2P_Cfg2_SW_Ver_Byte11_11 : 16|8@1+ (1,0) [0|255] ""  PC
 SG_ M2P_Cfg2_SW_Ver_Byte12_11 : 24|8@1+ (1,0) [0|255] ""  PC
 SG_ M2P_Cfg2_SW_Ver_Byte13_11 : 32|8@1+ (1,0) [0|255] ""  PC
 SG_ M2P_Cfg2_SW_Ver_Byte14_11 : 40|8@1+ (1,0) [0|255] ""  PC
 SG_ M2P_Cfg2_SW_Ver_Byte15_11 : 48|8@1+ (1,0) [0|255] ""  PC
 SG_ M2P_Cfg2_SW_Ver_Byte16_11 : 56|8@1+ (1,0) [0|255] ""  PC

BO_ 2416176796 M2P_Cfg2__12: 8 MBMU
 SG_ M2P_Cfg2_SW_Ver_Byte9_12 : 0|8@1+ (1,0) [0|255] ""  PC
 SG_ M2P_Cfg2_SW_Ver_Byte10_12 : 8|8@1+ (1,0) [0|255] ""  PC
 SG_ M2P_Cfg2_SW_Ver_Byte11_12 : 16|8@1+ (1,0) [0|255] ""  PC
 SG_ M2P_Cfg2_SW_Ver_Byte12_12 : 24|8@1+ (1,0) [0|255] ""  PC
 SG_ M2P_Cfg2_SW_Ver_Byte13_12 : 32|8@1+ (1,0) [0|255] ""  PC
 SG_ M2P_Cfg2_SW_Ver_Byte14_12 : 40|8@1+ (1,0) [0|255] ""  PC
 SG_ M2P_Cfg2_SW_Ver_Byte15_12 : 48|8@1+ (1,0) [0|255] ""  PC
 SG_ M2P_Cfg2_SW_Ver_Byte16_12 : 56|8@1+ (1,0) [0|255] ""  PC

BO_ 2416176797 M2P_Cfg2__13: 8 MBMU
 SG_ M2P_Cfg2_SW_Ver_Byte9_13 : 0|8@1+ (1,0) [0|255] ""  PC
 SG_ M2P_Cfg2_SW_Ver_Byte10_13 : 8|8@1+ (1,0) [0|255] ""  PC
 SG_ M2P_Cfg2_SW_Ver_Byte11_13 : 16|8@1+ (1,0) [0|255] ""  PC
 SG_ M2P_Cfg2_SW_Ver_Byte12_13 : 24|8@1+ (1,0) [0|255] ""  PC
 SG_ M2P_Cfg2_SW_Ver_Byte13_13 : 32|8@1+ (1,0) [0|255] ""  PC
 SG_ M2P_Cfg2_SW_Ver_Byte14_13 : 40|8@1+ (1,0) [0|255] ""  PC
 SG_ M2P_Cfg2_SW_Ver_Byte15_13 : 48|8@1+ (1,0) [0|255] ""  PC
 SG_ M2P_Cfg2_SW_Ver_Byte16_13 : 56|8@1+ (1,0) [0|255] ""  PC

BO_ 2416176798 M2P_Cfg2__14: 8 MBMU
 SG_ M2P_Cfg2_SW_Ver_Byte9_14 : 0|8@1+ (1,0) [0|255] ""  PC
 SG_ M2P_Cfg2_SW_Ver_Byte10_14 : 8|8@1+ (1,0) [0|255] ""  PC
 SG_ M2P_Cfg2_SW_Ver_Byte11_14 : 16|8@1+ (1,0) [0|255] ""  PC
 SG_ M2P_Cfg2_SW_Ver_Byte12_14 : 24|8@1+ (1,0) [0|255] ""  PC
 SG_ M2P_Cfg2_SW_Ver_Byte13_14 : 32|8@1+ (1,0) [0|255] ""  PC
 SG_ M2P_Cfg2_SW_Ver_Byte14_14 : 40|8@1+ (1,0) [0|255] ""  PC
 SG_ M2P_Cfg2_SW_Ver_Byte15_14 : 48|8@1+ (1,0) [0|255] ""  PC
 SG_ M2P_Cfg2_SW_Ver_Byte16_14 : 56|8@1+ (1,0) [0|255] ""  PC

BO_ 2416176799 M2P_Cfg2__15: 8 MBMU
 SG_ M2P_Cfg2_SW_Ver_Byte9_15 : 0|8@1+ (1,0) [0|255] ""  PC
 SG_ M2P_Cfg2_SW_Ver_Byte10_15 : 8|8@1+ (1,0) [0|255] ""  PC
 SG_ M2P_Cfg2_SW_Ver_Byte11_15 : 16|8@1+ (1,0) [0|255] ""  PC
 SG_ M2P_Cfg2_SW_Ver_Byte12_15 : 24|8@1+ (1,0) [0|255] ""  PC
 SG_ M2P_Cfg2_SW_Ver_Byte13_15 : 32|8@1+ (1,0) [0|255] ""  PC
 SG_ M2P_Cfg2_SW_Ver_Byte14_15 : 40|8@1+ (1,0) [0|255] ""  PC
 SG_ M2P_Cfg2_SW_Ver_Byte15_15 : 48|8@1+ (1,0) [0|255] ""  PC
 SG_ M2P_Cfg2_SW_Ver_Byte16_15 : 56|8@1+ (1,0) [0|255] ""  PC

BO_ 2416176800 M2P_Cfg2__16: 8 MBMU
 SG_ M2P_Cfg2_SW_Ver_Byte9_16 : 0|8@1+ (1,0) [0|255] ""  PC
 SG_ M2P_Cfg2_SW_Ver_Byte10_16 : 8|8@1+ (1,0) [0|255] ""  PC
 SG_ M2P_Cfg2_SW_Ver_Byte11_16 : 16|8@1+ (1,0) [0|255] ""  PC
 SG_ M2P_Cfg2_SW_Ver_Byte12_16 : 24|8@1+ (1,0) [0|255] ""  PC
 SG_ M2P_Cfg2_SW_Ver_Byte13_16 : 32|8@1+ (1,0) [0|255] ""  PC
 SG_ M2P_Cfg2_SW_Ver_Byte14_16 : 40|8@1+ (1,0) [0|255] ""  PC
 SG_ M2P_Cfg2_SW_Ver_Byte15_16 : 48|8@1+ (1,0) [0|255] ""  PC
 SG_ M2P_Cfg2_SW_Ver_Byte16_16 : 56|8@1+ (1,0) [0|255] ""  PC

BO_ 2416176801 M2P_Cfg2__17: 8 MBMU
 SG_ M2P_Cfg2_SW_Ver_Byte9_17 : 0|8@1+ (1,0) [0|255] ""  PC
 SG_ M2P_Cfg2_SW_Ver_Byte10_17 : 8|8@1+ (1,0) [0|255] ""  PC
 SG_ M2P_Cfg2_SW_Ver_Byte11_17 : 16|8@1+ (1,0) [0|255] ""  PC
 SG_ M2P_Cfg2_SW_Ver_Byte12_17 : 24|8@1+ (1,0) [0|255] ""  PC
 SG_ M2P_Cfg2_SW_Ver_Byte13_17 : 32|8@1+ (1,0) [0|255] ""  PC
 SG_ M2P_Cfg2_SW_Ver_Byte14_17 : 40|8@1+ (1,0) [0|255] ""  PC
 SG_ M2P_Cfg2_SW_Ver_Byte15_17 : 48|8@1+ (1,0) [0|255] ""  PC
 SG_ M2P_Cfg2_SW_Ver_Byte16_17 : 56|8@1+ (1,0) [0|255] ""  PC

BO_ 2416176802 M2P_Cfg2__18: 8 MBMU
 SG_ M2P_Cfg2_SW_Ver_Byte9_18 : 0|8@1+ (1,0) [0|255] ""  PC
 SG_ M2P_Cfg2_SW_Ver_Byte10_18 : 8|8@1+ (1,0) [0|255] ""  PC
 SG_ M2P_Cfg2_SW_Ver_Byte11_18 : 16|8@1+ (1,0) [0|255] ""  PC
 SG_ M2P_Cfg2_SW_Ver_Byte12_18 : 24|8@1+ (1,0) [0|255] ""  PC
 SG_ M2P_Cfg2_SW_Ver_Byte13_18 : 32|8@1+ (1,0) [0|255] ""  PC
 SG_ M2P_Cfg2_SW_Ver_Byte14_18 : 40|8@1+ (1,0) [0|255] ""  PC
 SG_ M2P_Cfg2_SW_Ver_Byte15_18 : 48|8@1+ (1,0) [0|255] ""  PC
 SG_ M2P_Cfg2_SW_Ver_Byte16_18 : 56|8@1+ (1,0) [0|255] ""  PC

BO_ 2416176803 M2P_Cfg2__19: 8 MBMU
 SG_ M2P_Cfg2_SW_Ver_Byte9_19 : 0|8@1+ (1,0) [0|255] ""  PC
 SG_ M2P_Cfg2_SW_Ver_Byte10_19 : 8|8@1+ (1,0) [0|255] ""  PC
 SG_ M2P_Cfg2_SW_Ver_Byte11_19 : 16|8@1+ (1,0) [0|255] ""  PC
 SG_ M2P_Cfg2_SW_Ver_Byte12_19 : 24|8@1+ (1,0) [0|255] ""  PC
 SG_ M2P_Cfg2_SW_Ver_Byte13_19 : 32|8@1+ (1,0) [0|255] ""  PC
 SG_ M2P_Cfg2_SW_Ver_Byte14_19 : 40|8@1+ (1,0) [0|255] ""  PC
 SG_ M2P_Cfg2_SW_Ver_Byte15_19 : 48|8@1+ (1,0) [0|255] ""  PC
 SG_ M2P_Cfg2_SW_Ver_Byte16_19 : 56|8@1+ (1,0) [0|255] ""  PC

BO_ 2416176804 M2P_Cfg2__20: 8 MBMU
 SG_ M2P_Cfg2_SW_Ver_Byte9_20 : 0|8@1+ (1,0) [0|255] ""  PC
 SG_ M2P_Cfg2_SW_Ver_Byte10_20 : 8|8@1+ (1,0) [0|255] ""  PC
 SG_ M2P_Cfg2_SW_Ver_Byte11_20 : 16|8@1+ (1,0) [0|255] ""  PC
 SG_ M2P_Cfg2_SW_Ver_Byte12_20 : 24|8@1+ (1,0) [0|255] ""  PC
 SG_ M2P_Cfg2_SW_Ver_Byte13_20 : 32|8@1+ (1,0) [0|255] ""  PC
 SG_ M2P_Cfg2_SW_Ver_Byte14_20 : 40|8@1+ (1,0) [0|255] ""  PC
 SG_ M2P_Cfg2_SW_Ver_Byte15_20 : 48|8@1+ (1,0) [0|255] ""  PC
 SG_ M2P_Cfg2_SW_Ver_Byte16_20 : 56|8@1+ (1,0) [0|255] ""  PC

BO_ 2416176805 M2P_Cfg2__21: 8 MBMU
 SG_ M2P_Cfg2_SW_Ver_Byte9_21 : 0|8@1+ (1,0) [0|255] ""  PC
 SG_ M2P_Cfg2_SW_Ver_Byte10_21 : 8|8@1+ (1,0) [0|255] ""  PC
 SG_ M2P_Cfg2_SW_Ver_Byte11_21 : 16|8@1+ (1,0) [0|255] ""  PC
 SG_ M2P_Cfg2_SW_Ver_Byte12_21 : 24|8@1+ (1,0) [0|255] ""  PC
 SG_ M2P_Cfg2_SW_Ver_Byte13_21 : 32|8@1+ (1,0) [0|255] ""  PC
 SG_ M2P_Cfg2_SW_Ver_Byte14_21 : 40|8@1+ (1,0) [0|255] ""  PC
 SG_ M2P_Cfg2_SW_Ver_Byte15_21 : 48|8@1+ (1,0) [0|255] ""  PC
 SG_ M2P_Cfg2_SW_Ver_Byte16_21 : 56|8@1+ (1,0) [0|255] ""  PC

BO_ 2416176806 M2P_Cfg2__22: 8 MBMU
 SG_ M2P_Cfg2_SW_Ver_Byte9_22 : 0|8@1+ (1,0) [0|255] ""  PC
 SG_ M2P_Cfg2_SW_Ver_Byte10_22 : 8|8@1+ (1,0) [0|255] ""  PC
 SG_ M2P_Cfg2_SW_Ver_Byte11_22 : 16|8@1+ (1,0) [0|255] ""  PC
 SG_ M2P_Cfg2_SW_Ver_Byte12_22 : 24|8@1+ (1,0) [0|255] ""  PC
 SG_ M2P_Cfg2_SW_Ver_Byte13_22 : 32|8@1+ (1,0) [0|255] ""  PC
 SG_ M2P_Cfg2_SW_Ver_Byte14_22 : 40|8@1+ (1,0) [0|255] ""  PC
 SG_ M2P_Cfg2_SW_Ver_Byte15_22 : 48|8@1+ (1,0) [0|255] ""  PC
 SG_ M2P_Cfg2_SW_Ver_Byte16_22 : 56|8@1+ (1,0) [0|255] ""  PC

BO_ 2416176807 M2P_Cfg2__23: 8 MBMU
 SG_ M2P_Cfg2_SW_Ver_Byte9_23 : 0|8@1+ (1,0) [0|255] ""  PC
 SG_ M2P_Cfg2_SW_Ver_Byte10_23 : 8|8@1+ (1,0) [0|255] ""  PC
 SG_ M2P_Cfg2_SW_Ver_Byte11_23 : 16|8@1+ (1,0) [0|255] ""  PC
 SG_ M2P_Cfg2_SW_Ver_Byte12_23 : 24|8@1+ (1,0) [0|255] ""  PC
 SG_ M2P_Cfg2_SW_Ver_Byte13_23 : 32|8@1+ (1,0) [0|255] ""  PC
 SG_ M2P_Cfg2_SW_Ver_Byte14_23 : 40|8@1+ (1,0) [0|255] ""  PC
 SG_ M2P_Cfg2_SW_Ver_Byte15_23 : 48|8@1+ (1,0) [0|255] ""  PC
 SG_ M2P_Cfg2_SW_Ver_Byte16_23 : 56|8@1+ (1,0) [0|255] ""  PC

BO_ 2416176808 M2P_Cfg2__24: 8 MBMU
 SG_ M2P_Cfg2_SW_Ver_Byte9_24 : 0|8@1+ (1,0) [0|255] ""  PC
 SG_ M2P_Cfg2_SW_Ver_Byte10_24 : 8|8@1+ (1,0) [0|255] ""  PC
 SG_ M2P_Cfg2_SW_Ver_Byte11_24 : 16|8@1+ (1,0) [0|255] ""  PC
 SG_ M2P_Cfg2_SW_Ver_Byte12_24 : 24|8@1+ (1,0) [0|255] ""  PC
 SG_ M2P_Cfg2_SW_Ver_Byte13_24 : 32|8@1+ (1,0) [0|255] ""  PC
 SG_ M2P_Cfg2_SW_Ver_Byte14_24 : 40|8@1+ (1,0) [0|255] ""  PC
 SG_ M2P_Cfg2_SW_Ver_Byte15_24 : 48|8@1+ (1,0) [0|255] ""  PC
 SG_ M2P_Cfg2_SW_Ver_Byte16_24 : 56|8@1+ (1,0) [0|255] ""  PC

BO_ 2416176809 M2P_Cfg2__25: 8 MBMU
 SG_ M2P_Cfg2_SW_Ver_Byte9_25 : 0|8@1+ (1,0) [0|255] ""  PC
 SG_ M2P_Cfg2_SW_Ver_Byte10_25 : 8|8@1+ (1,0) [0|255] ""  PC
 SG_ M2P_Cfg2_SW_Ver_Byte11_25 : 16|8@1+ (1,0) [0|255] ""  PC
 SG_ M2P_Cfg2_SW_Ver_Byte12_25 : 24|8@1+ (1,0) [0|255] ""  PC
 SG_ M2P_Cfg2_SW_Ver_Byte13_25 : 32|8@1+ (1,0) [0|255] ""  PC
 SG_ M2P_Cfg2_SW_Ver_Byte14_25 : 40|8@1+ (1,0) [0|255] ""  PC
 SG_ M2P_Cfg2_SW_Ver_Byte15_25 : 48|8@1+ (1,0) [0|255] ""  PC
 SG_ M2P_Cfg2_SW_Ver_Byte16_25 : 56|8@1+ (1,0) [0|255] ""  PC

BO_ 2416176810 M2P_Cfg2__26: 8 MBMU
 SG_ M2P_Cfg2_SW_Ver_Byte9_26 : 0|8@1+ (1,0) [0|255] ""  PC
 SG_ M2P_Cfg2_SW_Ver_Byte10_26 : 8|8@1+ (1,0) [0|255] ""  PC
 SG_ M2P_Cfg2_SW_Ver_Byte11_26 : 16|8@1+ (1,0) [0|255] ""  PC
 SG_ M2P_Cfg2_SW_Ver_Byte12_26 : 24|8@1+ (1,0) [0|255] ""  PC
 SG_ M2P_Cfg2_SW_Ver_Byte13_26 : 32|8@1+ (1,0) [0|255] ""  PC
 SG_ M2P_Cfg2_SW_Ver_Byte14_26 : 40|8@1+ (1,0) [0|255] ""  PC
 SG_ M2P_Cfg2_SW_Ver_Byte15_26 : 48|8@1+ (1,0) [0|255] ""  PC
 SG_ M2P_Cfg2_SW_Ver_Byte16_26 : 56|8@1+ (1,0) [0|255] ""  PC

BO_ 2416176811 M2P_Cfg2__27: 8 MBMU
 SG_ M2P_Cfg2_SW_Ver_Byte9_27 : 0|8@1+ (1,0) [0|255] ""  PC
 SG_ M2P_Cfg2_SW_Ver_Byte10_27 : 8|8@1+ (1,0) [0|255] ""  PC
 SG_ M2P_Cfg2_SW_Ver_Byte11_27 : 16|8@1+ (1,0) [0|255] ""  PC
 SG_ M2P_Cfg2_SW_Ver_Byte12_27 : 24|8@1+ (1,0) [0|255] ""  PC
 SG_ M2P_Cfg2_SW_Ver_Byte13_27 : 32|8@1+ (1,0) [0|255] ""  PC
 SG_ M2P_Cfg2_SW_Ver_Byte14_27 : 40|8@1+ (1,0) [0|255] ""  PC
 SG_ M2P_Cfg2_SW_Ver_Byte15_27 : 48|8@1+ (1,0) [0|255] ""  PC
 SG_ M2P_Cfg2_SW_Ver_Byte16_27 : 56|8@1+ (1,0) [0|255] ""  PC

BO_ 2416176812 M2P_Cfg2__28: 8 MBMU
 SG_ M2P_Cfg2_SW_Ver_Byte9_28 : 0|8@1+ (1,0) [0|255] ""  PC
 SG_ M2P_Cfg2_SW_Ver_Byte10_28 : 8|8@1+ (1,0) [0|255] ""  PC
 SG_ M2P_Cfg2_SW_Ver_Byte11_28 : 16|8@1+ (1,0) [0|255] ""  PC
 SG_ M2P_Cfg2_SW_Ver_Byte12_28 : 24|8@1+ (1,0) [0|255] ""  PC
 SG_ M2P_Cfg2_SW_Ver_Byte13_28 : 32|8@1+ (1,0) [0|255] ""  PC
 SG_ M2P_Cfg2_SW_Ver_Byte14_28 : 40|8@1+ (1,0) [0|255] ""  PC
 SG_ M2P_Cfg2_SW_Ver_Byte15_28 : 48|8@1+ (1,0) [0|255] ""  PC
 SG_ M2P_Cfg2_SW_Ver_Byte16_28 : 56|8@1+ (1,0) [0|255] ""  PC

BO_ 2416176813 M2P_Cfg2__29: 8 MBMU
 SG_ M2P_Cfg2_SW_Ver_Byte9_29 : 0|8@1+ (1,0) [0|255] ""  PC
 SG_ M2P_Cfg2_SW_Ver_Byte10_29 : 8|8@1+ (1,0) [0|255] ""  PC
 SG_ M2P_Cfg2_SW_Ver_Byte11_29 : 16|8@1+ (1,0) [0|255] ""  PC
 SG_ M2P_Cfg2_SW_Ver_Byte12_29 : 24|8@1+ (1,0) [0|255] ""  PC
 SG_ M2P_Cfg2_SW_Ver_Byte13_29 : 32|8@1+ (1,0) [0|255] ""  PC
 SG_ M2P_Cfg2_SW_Ver_Byte14_29 : 40|8@1+ (1,0) [0|255] ""  PC
 SG_ M2P_Cfg2_SW_Ver_Byte15_29 : 48|8@1+ (1,0) [0|255] ""  PC
 SG_ M2P_Cfg2_SW_Ver_Byte16_29 : 56|8@1+ (1,0) [0|255] ""  PC

BO_ 2416176814 M2P_Cfg2__30: 8 MBMU
 SG_ M2P_Cfg2_SW_Ver_Byte9_30 : 0|8@1+ (1,0) [0|255] ""  PC
 SG_ M2P_Cfg2_SW_Ver_Byte10_30 : 8|8@1+ (1,0) [0|255] ""  PC
 SG_ M2P_Cfg2_SW_Ver_Byte11_30 : 16|8@1+ (1,0) [0|255] ""  PC
 SG_ M2P_Cfg2_SW_Ver_Byte12_30 : 24|8@1+ (1,0) [0|255] ""  PC
 SG_ M2P_Cfg2_SW_Ver_Byte13_30 : 32|8@1+ (1,0) [0|255] ""  PC
 SG_ M2P_Cfg2_SW_Ver_Byte14_30 : 40|8@1+ (1,0) [0|255] ""  PC
 SG_ M2P_Cfg2_SW_Ver_Byte15_30 : 48|8@1+ (1,0) [0|255] ""  PC
 SG_ M2P_Cfg2_SW_Ver_Byte16_30 : 56|8@1+ (1,0) [0|255] ""  PC

BO_ 2416176815 M2P_Cfg2__31: 8 MBMU
 SG_ M2P_Cfg2_SW_Ver_Byte9_31 : 0|8@1+ (1,0) [0|255] ""  PC
 SG_ M2P_Cfg2_SW_Ver_Byte10_31 : 8|8@1+ (1,0) [0|255] ""  PC
 SG_ M2P_Cfg2_SW_Ver_Byte11_31 : 16|8@1+ (1,0) [0|255] ""  PC
 SG_ M2P_Cfg2_SW_Ver_Byte12_31 : 24|8@1+ (1,0) [0|255] ""  PC
 SG_ M2P_Cfg2_SW_Ver_Byte13_31 : 32|8@1+ (1,0) [0|255] ""  PC
 SG_ M2P_Cfg2_SW_Ver_Byte14_31 : 40|8@1+ (1,0) [0|255] ""  PC
 SG_ M2P_Cfg2_SW_Ver_Byte15_31 : 48|8@1+ (1,0) [0|255] ""  PC
 SG_ M2P_Cfg2_SW_Ver_Byte16_31 : 56|8@1+ (1,0) [0|255] ""  PC

BO_ 2416242321 M2P_Cfg3__01: 8 MBMU
 SG_ M2P_Cfg3_HW_Ver_Byte1_01 : 0|8@1+ (1,0) [0|255] ""  PC
 SG_ M2P_Cfg3_HW_Ver_Byte2_01 : 8|8@1+ (1,0) [0|255] ""  PC
 SG_ M2P_Cfg3_HW_Ver_Byte3_01 : 16|8@1+ (1,0) [0|255] ""  PC
 SG_ M2P_Cfg3_HW_Ver_Byte4_01 : 24|8@1+ (1,0) [0|255] ""  PC
 SG_ M2P_Cfg3_HW_Ver_Byte5_01 : 32|8@1+ (1,0) [0|255] ""  PC
 SG_ M2P_Cfg3_HW_Ver_Byte6_01 : 40|8@1+ (1,0) [0|255] ""  PC
 SG_ M2P_Cfg3_HW_Ver_Byte7_01 : 48|8@1+ (1,0) [0|255] ""  PC
 SG_ M2P_Cfg3_HW_Ver_Byte8_01 : 56|8@1+ (1,0) [0|255] ""  PC

BO_ 2416242322 M2P_Cfg3__02: 8 MBMU
 SG_ M2P_Cfg3_HW_Ver_Byte1_02 : 0|8@1+ (1,0) [0|255] ""  PC
 SG_ M2P_Cfg3_HW_Ver_Byte2_02 : 8|8@1+ (1,0) [0|255] ""  PC
 SG_ M2P_Cfg3_HW_Ver_Byte3_02 : 16|8@1+ (1,0) [0|255] ""  PC
 SG_ M2P_Cfg3_HW_Ver_Byte4_02 : 24|8@1+ (1,0) [0|255] ""  PC
 SG_ M2P_Cfg3_HW_Ver_Byte5_02 : 32|8@1+ (1,0) [0|255] ""  PC
 SG_ M2P_Cfg3_HW_Ver_Byte6_02 : 40|8@1+ (1,0) [0|255] ""  PC
 SG_ M2P_Cfg3_HW_Ver_Byte7_02 : 48|8@1+ (1,0) [0|255] ""  PC
 SG_ M2P_Cfg3_HW_Ver_Byte8_02 : 56|8@1+ (1,0) [0|255] ""  PC

BO_ 2416242323 M2P_Cfg3__03: 8 MBMU
 SG_ M2P_Cfg3_HW_Ver_Byte1_03 : 0|8@1+ (1,0) [0|255] ""  PC
 SG_ M2P_Cfg3_HW_Ver_Byte2_03 : 8|8@1+ (1,0) [0|255] ""  PC
 SG_ M2P_Cfg3_HW_Ver_Byte3_03 : 16|8@1+ (1,0) [0|255] ""  PC
 SG_ M2P_Cfg3_HW_Ver_Byte4_03 : 24|8@1+ (1,0) [0|255] ""  PC
 SG_ M2P_Cfg3_HW_Ver_Byte5_03 : 32|8@1+ (1,0) [0|255] ""  PC
 SG_ M2P_Cfg3_HW_Ver_Byte6_03 : 40|8@1+ (1,0) [0|255] ""  PC
 SG_ M2P_Cfg3_HW_Ver_Byte7_03 : 48|8@1+ (1,0) [0|255] ""  PC
 SG_ M2P_Cfg3_HW_Ver_Byte8_03 : 56|8@1+ (1,0) [0|255] ""  PC

BO_ 2416242324 M2P_Cfg3__04: 8 MBMU
 SG_ M2P_Cfg3_HW_Ver_Byte1_04 : 0|8@1+ (1,0) [0|255] ""  PC
 SG_ M2P_Cfg3_HW_Ver_Byte2_04 : 8|8@1+ (1,0) [0|255] ""  PC
 SG_ M2P_Cfg3_HW_Ver_Byte3_04 : 16|8@1+ (1,0) [0|255] ""  PC
 SG_ M2P_Cfg3_HW_Ver_Byte4_04 : 24|8@1+ (1,0) [0|255] ""  PC
 SG_ M2P_Cfg3_HW_Ver_Byte5_04 : 32|8@1+ (1,0) [0|255] ""  PC
 SG_ M2P_Cfg3_HW_Ver_Byte6_04 : 40|8@1+ (1,0) [0|255] ""  PC
 SG_ M2P_Cfg3_HW_Ver_Byte7_04 : 48|8@1+ (1,0) [0|255] ""  PC
 SG_ M2P_Cfg3_HW_Ver_Byte8_04 : 56|8@1+ (1,0) [0|255] ""  PC

BO_ 2416242325 M2P_Cfg3__05: 8 MBMU
 SG_ M2P_Cfg3_HW_Ver_Byte1_05 : 0|8@1+ (1,0) [0|255] ""  PC
 SG_ M2P_Cfg3_HW_Ver_Byte2_05 : 8|8@1+ (1,0) [0|255] ""  PC
 SG_ M2P_Cfg3_HW_Ver_Byte3_05 : 16|8@1+ (1,0) [0|255] ""  PC
 SG_ M2P_Cfg3_HW_Ver_Byte4_05 : 24|8@1+ (1,0) [0|255] ""  PC
 SG_ M2P_Cfg3_HW_Ver_Byte5_05 : 32|8@1+ (1,0) [0|255] ""  PC
 SG_ M2P_Cfg3_HW_Ver_Byte6_05 : 40|8@1+ (1,0) [0|255] ""  PC
 SG_ M2P_Cfg3_HW_Ver_Byte7_05 : 48|8@1+ (1,0) [0|255] ""  PC
 SG_ M2P_Cfg3_HW_Ver_Byte8_05 : 56|8@1+ (1,0) [0|255] ""  PC

BO_ 2416242326 M2P_Cfg3__06: 8 MBMU
 SG_ M2P_Cfg3_HW_Ver_Byte1_06 : 0|8@1+ (1,0) [0|255] ""  PC
 SG_ M2P_Cfg3_HW_Ver_Byte2_06 : 8|8@1+ (1,0) [0|255] ""  PC
 SG_ M2P_Cfg3_HW_Ver_Byte3_06 : 16|8@1+ (1,0) [0|255] ""  PC
 SG_ M2P_Cfg3_HW_Ver_Byte4_06 : 24|8@1+ (1,0) [0|255] ""  PC
 SG_ M2P_Cfg3_HW_Ver_Byte5_06 : 32|8@1+ (1,0) [0|255] ""  PC
 SG_ M2P_Cfg3_HW_Ver_Byte6_06 : 40|8@1+ (1,0) [0|255] ""  PC
 SG_ M2P_Cfg3_HW_Ver_Byte7_06 : 48|8@1+ (1,0) [0|255] ""  PC
 SG_ M2P_Cfg3_HW_Ver_Byte8_06 : 56|8@1+ (1,0) [0|255] ""  PC

BO_ 2416242327 M2P_Cfg3__07: 8 MBMU
 SG_ M2P_Cfg3_HW_Ver_Byte1_07 : 0|8@1+ (1,0) [0|255] ""  PC
 SG_ M2P_Cfg3_HW_Ver_Byte2_07 : 8|8@1+ (1,0) [0|255] ""  PC
 SG_ M2P_Cfg3_HW_Ver_Byte3_07 : 16|8@1+ (1,0) [0|255] ""  PC
 SG_ M2P_Cfg3_HW_Ver_Byte4_07 : 24|8@1+ (1,0) [0|255] ""  PC
 SG_ M2P_Cfg3_HW_Ver_Byte5_07 : 32|8@1+ (1,0) [0|255] ""  PC
 SG_ M2P_Cfg3_HW_Ver_Byte6_07 : 40|8@1+ (1,0) [0|255] ""  PC
 SG_ M2P_Cfg3_HW_Ver_Byte7_07 : 48|8@1+ (1,0) [0|255] ""  PC
 SG_ M2P_Cfg3_HW_Ver_Byte8_07 : 56|8@1+ (1,0) [0|255] ""  PC

BO_ 2416242328 M2P_Cfg3__08: 8 MBMU
 SG_ M2P_Cfg3_HW_Ver_Byte1_08 : 0|8@1+ (1,0) [0|255] ""  PC
 SG_ M2P_Cfg3_HW_Ver_Byte2_08 : 8|8@1+ (1,0) [0|255] ""  PC
 SG_ M2P_Cfg3_HW_Ver_Byte3_08 : 16|8@1+ (1,0) [0|255] ""  PC
 SG_ M2P_Cfg3_HW_Ver_Byte4_08 : 24|8@1+ (1,0) [0|255] ""  PC
 SG_ M2P_Cfg3_HW_Ver_Byte5_08 : 32|8@1+ (1,0) [0|255] ""  PC
 SG_ M2P_Cfg3_HW_Ver_Byte6_08 : 40|8@1+ (1,0) [0|255] ""  PC
 SG_ M2P_Cfg3_HW_Ver_Byte7_08 : 48|8@1+ (1,0) [0|255] ""  PC
 SG_ M2P_Cfg3_HW_Ver_Byte8_08 : 56|8@1+ (1,0) [0|255] ""  PC

BO_ 2416242329 M2P_Cfg3__09: 8 MBMU
 SG_ M2P_Cfg3_HW_Ver_Byte1_09 : 0|8@1+ (1,0) [0|255] ""  PC
 SG_ M2P_Cfg3_HW_Ver_Byte2_09 : 8|8@1+ (1,0) [0|255] ""  PC
 SG_ M2P_Cfg3_HW_Ver_Byte3_09 : 16|8@1+ (1,0) [0|255] ""  PC
 SG_ M2P_Cfg3_HW_Ver_Byte4_09 : 24|8@1+ (1,0) [0|255] ""  PC
 SG_ M2P_Cfg3_HW_Ver_Byte5_09 : 32|8@1+ (1,0) [0|255] ""  PC
 SG_ M2P_Cfg3_HW_Ver_Byte6_09 : 40|8@1+ (1,0) [0|255] ""  PC
 SG_ M2P_Cfg3_HW_Ver_Byte7_09 : 48|8@1+ (1,0) [0|255] ""  PC
 SG_ M2P_Cfg3_HW_Ver_Byte8_09 : 56|8@1+ (1,0) [0|255] ""  PC

BO_ 2416242330 M2P_Cfg3__10: 8 MBMU
 SG_ M2P_Cfg3_HW_Ver_Byte1_10 : 0|8@1+ (1,0) [0|255] ""  PC
 SG_ M2P_Cfg3_HW_Ver_Byte2_10 : 8|8@1+ (1,0) [0|255] ""  PC
 SG_ M2P_Cfg3_HW_Ver_Byte3_10 : 16|8@1+ (1,0) [0|255] ""  PC
 SG_ M2P_Cfg3_HW_Ver_Byte4_10 : 24|8@1+ (1,0) [0|255] ""  PC
 SG_ M2P_Cfg3_HW_Ver_Byte5_10 : 32|8@1+ (1,0) [0|255] ""  PC
 SG_ M2P_Cfg3_HW_Ver_Byte6_10 : 40|8@1+ (1,0) [0|255] ""  PC
 SG_ M2P_Cfg3_HW_Ver_Byte7_10 : 48|8@1+ (1,0) [0|255] ""  PC
 SG_ M2P_Cfg3_HW_Ver_Byte8_10 : 56|8@1+ (1,0) [0|255] ""  PC

BO_ 2416242331 M2P_Cfg3__11: 8 MBMU
 SG_ M2P_Cfg3_HW_Ver_Byte1_11 : 0|8@1+ (1,0) [0|255] ""  PC
 SG_ M2P_Cfg3_HW_Ver_Byte2_11 : 8|8@1+ (1,0) [0|255] ""  PC
 SG_ M2P_Cfg3_HW_Ver_Byte3_11 : 16|8@1+ (1,0) [0|255] ""  PC
 SG_ M2P_Cfg3_HW_Ver_Byte4_11 : 24|8@1+ (1,0) [0|255] ""  PC
 SG_ M2P_Cfg3_HW_Ver_Byte5_11 : 32|8@1+ (1,0) [0|255] ""  PC
 SG_ M2P_Cfg3_HW_Ver_Byte6_11 : 40|8@1+ (1,0) [0|255] ""  PC
 SG_ M2P_Cfg3_HW_Ver_Byte7_11 : 48|8@1+ (1,0) [0|255] ""  PC
 SG_ M2P_Cfg3_HW_Ver_Byte8_11 : 56|8@1+ (1,0) [0|255] ""  PC

BO_ 2416242332 M2P_Cfg3__12: 8 MBMU
 SG_ M2P_Cfg3_HW_Ver_Byte1_12 : 0|8@1+ (1,0) [0|255] ""  PC
 SG_ M2P_Cfg3_HW_Ver_Byte2_12 : 8|8@1+ (1,0) [0|255] ""  PC
 SG_ M2P_Cfg3_HW_Ver_Byte3_12 : 16|8@1+ (1,0) [0|255] ""  PC
 SG_ M2P_Cfg3_HW_Ver_Byte4_12 : 24|8@1+ (1,0) [0|255] ""  PC
 SG_ M2P_Cfg3_HW_Ver_Byte5_12 : 32|8@1+ (1,0) [0|255] ""  PC
 SG_ M2P_Cfg3_HW_Ver_Byte6_12 : 40|8@1+ (1,0) [0|255] ""  PC
 SG_ M2P_Cfg3_HW_Ver_Byte7_12 : 48|8@1+ (1,0) [0|255] ""  PC
 SG_ M2P_Cfg3_HW_Ver_Byte8_12 : 56|8@1+ (1,0) [0|255] ""  PC

BO_ 2416242333 M2P_Cfg3__13: 8 MBMU
 SG_ M2P_Cfg3_HW_Ver_Byte1_13 : 0|8@1+ (1,0) [0|255] ""  PC
 SG_ M2P_Cfg3_HW_Ver_Byte2_13 : 8|8@1+ (1,0) [0|255] ""  PC
 SG_ M2P_Cfg3_HW_Ver_Byte3_13 : 16|8@1+ (1,0) [0|255] ""  PC
 SG_ M2P_Cfg3_HW_Ver_Byte4_13 : 24|8@1+ (1,0) [0|255] ""  PC
 SG_ M2P_Cfg3_HW_Ver_Byte5_13 : 32|8@1+ (1,0) [0|255] ""  PC
 SG_ M2P_Cfg3_HW_Ver_Byte6_13 : 40|8@1+ (1,0) [0|255] ""  PC
 SG_ M2P_Cfg3_HW_Ver_Byte7_13 : 48|8@1+ (1,0) [0|255] ""  PC
 SG_ M2P_Cfg3_HW_Ver_Byte8_13 : 56|8@1+ (1,0) [0|255] ""  PC

BO_ 2416242334 M2P_Cfg3__14: 8 MBMU
 SG_ M2P_Cfg3_HW_Ver_Byte1_14 : 0|8@1+ (1,0) [0|255] ""  PC
 SG_ M2P_Cfg3_HW_Ver_Byte2_14 : 8|8@1+ (1,0) [0|255] ""  PC
 SG_ M2P_Cfg3_HW_Ver_Byte3_14 : 16|8@1+ (1,0) [0|255] ""  PC
 SG_ M2P_Cfg3_HW_Ver_Byte4_14 : 24|8@1+ (1,0) [0|255] ""  PC
 SG_ M2P_Cfg3_HW_Ver_Byte5_14 : 32|8@1+ (1,0) [0|255] ""  PC
 SG_ M2P_Cfg3_HW_Ver_Byte6_14 : 40|8@1+ (1,0) [0|255] ""  PC
 SG_ M2P_Cfg3_HW_Ver_Byte7_14 : 48|8@1+ (1,0) [0|255] ""  PC
 SG_ M2P_Cfg3_HW_Ver_Byte8_14 : 56|8@1+ (1,0) [0|255] ""  PC

BO_ 2416242335 M2P_Cfg3__15: 8 MBMU
 SG_ M2P_Cfg3_HW_Ver_Byte1_15 : 0|8@1+ (1,0) [0|255] ""  PC
 SG_ M2P_Cfg3_HW_Ver_Byte2_15 : 8|8@1+ (1,0) [0|255] ""  PC
 SG_ M2P_Cfg3_HW_Ver_Byte3_15 : 16|8@1+ (1,0) [0|255] ""  PC
 SG_ M2P_Cfg3_HW_Ver_Byte4_15 : 24|8@1+ (1,0) [0|255] ""  PC
 SG_ M2P_Cfg3_HW_Ver_Byte5_15 : 32|8@1+ (1,0) [0|255] ""  PC
 SG_ M2P_Cfg3_HW_Ver_Byte6_15 : 40|8@1+ (1,0) [0|255] ""  PC
 SG_ M2P_Cfg3_HW_Ver_Byte7_15 : 48|8@1+ (1,0) [0|255] ""  PC
 SG_ M2P_Cfg3_HW_Ver_Byte8_15 : 56|8@1+ (1,0) [0|255] ""  PC

BO_ 2416242336 M2P_Cfg3__16: 8 MBMU
 SG_ M2P_Cfg3_HW_Ver_Byte1_16 : 0|8@1+ (1,0) [0|255] ""  PC
 SG_ M2P_Cfg3_HW_Ver_Byte2_16 : 8|8@1+ (1,0) [0|255] ""  PC
 SG_ M2P_Cfg3_HW_Ver_Byte3_16 : 16|8@1+ (1,0) [0|255] ""  PC
 SG_ M2P_Cfg3_HW_Ver_Byte4_16 : 24|8@1+ (1,0) [0|255] ""  PC
 SG_ M2P_Cfg3_HW_Ver_Byte5_16 : 32|8@1+ (1,0) [0|255] ""  PC
 SG_ M2P_Cfg3_HW_Ver_Byte6_16 : 40|8@1+ (1,0) [0|255] ""  PC
 SG_ M2P_Cfg3_HW_Ver_Byte7_16 : 48|8@1+ (1,0) [0|255] ""  PC
 SG_ M2P_Cfg3_HW_Ver_Byte8_16 : 56|8@1+ (1,0) [0|255] ""  PC

CM_ SG_ 2332552875 M2P_SysremainEngy_Charge_27 "系统充电剩余能量";
CM_ SG_ 2332552875 M2P_SysremainEngy_DisCharge_27 "系统放电剩余能量";
CM_ SG_ 2332552875 M2P_SOE_Charge_27 "系统可充电SOE";
CM_ SG_ 2332552875 M2P_SOE_Discharge_27 "系统可放电SOE";
CM_ SG_ 2332552876 M2P_SysremainEngy_Charge_28 "系统充电剩余能量";
CM_ SG_ 2332552876 M2P_SysremainEngy_DisCharge_28 "系统放电剩余能量";
CM_ SG_ 2332552876 M2P_SOE_Charge_28 "系统可充电SOE";
CM_ SG_ 2332552876 M2P_SOE_Discharge_28 "系统可放电SOE";
CM_ SG_ 2332552877 M2P_SysremainEngy_Charge_29 "系统充电剩余能量";
CM_ SG_ 2332552877 M2P_SysremainEngy_DisCharge_29 "系统放电剩余能量";
CM_ SG_ 2332552877 M2P_SOE_Charge_29 "系统可充电SOE";
CM_ SG_ 2332552877 M2P_SOE_Discharge_29 "系统可放电SOE";
CM_ SG_ 2332552878 M2P_SysremainEngy_Charge_30 "系统充电剩余能量";
CM_ SG_ 2332552878 M2P_SysremainEngy_DisCharge_30 "系统放电剩余能量";
CM_ SG_ 2332552878 M2P_SOE_Charge_30 "系统可充电SOE";
CM_ SG_ 2332552878 M2P_SOE_Discharge_30 "系统可放电SOE";
CM_ SG_ 2332552879 M2P_SysremainEngy_Charge_31 "系统充电剩余能量";
CM_ SG_ 2332552879 M2P_SysremainEngy_DisCharge_31 "系统放电剩余能量";
CM_ SG_ 2332552879 M2P_SOE_Charge_31 "系统可充电SOE";
CM_ SG_ 2332552879 M2P_SOE_Discharge_31 "系统可放电SOE";
CM_ SG_ 2400382609 M2P_HisChgCap "历史充电累积容量";
CM_ SG_ 2400382609 M2P_HisDchgCap "历史放电累积容量";
CM_ SG_ 2400382610 M2P_HisChgCap "历史充电累积容量";
CM_ SG_ 2400382610 M2P_HisDchgCap "历史放电累积容量";
CM_ SG_ 2400382611 M2P_HisChgCap "历史充电累积容量";
CM_ SG_ 2400382611 M2P_HisDchgCap "历史放电累积容量";
CM_ SG_ 2400382612 M2P_HisChgCap "历史充电累积容量";
CM_ SG_ 2400382612 M2P_HisDchgCap "历史放电累积容量";
CM_ SG_ 2400382613 M2P_HisChgCap "历史充电累积容量";
CM_ SG_ 2400382613 M2P_HisDchgCap "历史放电累积容量";
CM_ SG_ 2400382614 M2P_HisChgCap "历史充电累积容量";
CM_ SG_ 2400382614 M2P_HisDchgCap "历史放电累积容量";
CM_ SG_ 2400382615 M2P_HisChgCap "历史充电累积容量";
CM_ SG_ 2400382615 M2P_HisDchgCap "历史放电累积容量";
CM_ SG_ 2400382616 M2P_HisChgCap "历史充电累积容量";
CM_ SG_ 2400382616 M2P_HisDchgCap "历史放电累积容量";
CM_ SG_ 2400382617 M2P_HisChgCap "历史充电累积容量";
CM_ SG_ 2400382617 M2P_HisDchgCap "历史放电累积容量";
CM_ SG_ 2400382618 M2P_HisChgCap "历史充电累积容量";
CM_ SG_ 2400382618 M2P_HisDchgCap "历史放电累积容量";
CM_ SG_ 2400382619 M2P_HisChgCap "历史充电累积容量";
CM_ SG_ 2400382619 M2P_HisDchgCap "历史放电累积容量";
CM_ SG_ 2400382620 M2P_HisChgCap "历史充电累积容量";
CM_ SG_ 2400382620 M2P_HisDchgCap "历史放电累积容量";
CM_ SG_ 2400382621 M2P_HisChgCap "历史充电累积容量";
CM_ SG_ 2400382621 M2P_HisDchgCap "历史放电累积容量";
CM_ SG_ 2400382622 M2P_HisChgCap "历史充电累积容量";
CM_ SG_ 2400382622 M2P_HisDchgCap "历史放电累积容量";
CM_ SG_ 2400382623 M2P_HisChgCap "历史充电累积容量";
CM_ SG_ 2400382623 M2P_HisDchgCap "历史放电累积容量";
CM_ SG_ 2400382624 M2P_HisChgCap "历史充电累积容量";
CM_ SG_ 2400382624 M2P_HisDchgCap "历史放电累积容量";
CM_ SG_ 2400382625 M2P_HisChgCap "历史充电累积容量";
CM_ SG_ 2400382625 M2P_HisDchgCap "历史放电累积容量";
CM_ SG_ 2400382626 M2P_HisChgCap "历史充电累积容量";
CM_ SG_ 2400382626 M2P_HisDchgCap "历史放电累积容量";
CM_ SG_ 2400382627 M2P_HisChgCap "历史充电累积容量";
CM_ SG_ 2400382627 M2P_HisDchgCap "历史放电累积容量";
CM_ SG_ 2400382628 M2P_HisChgCap "历史充电累积容量";
CM_ SG_ 2400382628 M2P_HisDchgCap "历史放电累积容量";
CM_ SG_ 2400382629 M2P_HisChgCap "历史充电累积容量";
CM_ SG_ 2400382629 M2P_HisDchgCap "历史放电累积容量";
CM_ SG_ 2400382630 M2P_HisChgCap "历史充电累积容量";
CM_ SG_ 2400382630 M2P_HisDchgCap "历史放电累积容量";
CM_ SG_ 2400382631 M2P_HisChgCap "历史充电累积容量";
CM_ SG_ 2400382631 M2P_HisDchgCap "历史放电累积容量";
CM_ SG_ 2400382632 M2P_HisChgCap "历史充电累积容量";
CM_ SG_ 2400382632 M2P_HisDchgCap "历史放电累积容量";
CM_ SG_ 2400382633 M2P_HisChgCap "历史充电累积容量";
CM_ SG_ 2400382633 M2P_HisDchgCap "历史放电累积容量";
CM_ SG_ 2400382634 M2P_HisChgCap "历史充电累积容量";
CM_ SG_ 2400382634 M2P_HisDchgCap "历史放电累积容量";
CM_ SG_ 2400382635 M2P_HisChgCap "历史充电累积容量";
CM_ SG_ 2400382635 M2P_HisDchgCap "历史放电累积容量";
CM_ SG_ 2400382636 M2P_HisChgCap "历史充电累积容量";
CM_ SG_ 2400382636 M2P_HisDchgCap "历史放电累积容量";
CM_ SG_ 2400382637 M2P_HisChgCap "历史充电累积容量";
CM_ SG_ 2400382637 M2P_HisDchgCap "历史放电累积容量";
CM_ SG_ 2400382638 M2P_HisChgCap "历史充电累积容量";
CM_ SG_ 2400382638 M2P_HisDchgCap "历史放电累积容量";
CM_ SG_ 2400382639 M2P_HisChgCap "历史充电累积容量";
CM_ SG_ 2400382639 M2P_HisDchgCap "历史放电累积容量";
CM_ SG_ 2415980177 M2P_Response_Byte1_01 "MBMU给PC的反馈信息1,新增功能使用： 0xA0  反馈写入结果  ，0x50反馈读取结果；
如果需要反馈多报文，使用0x51，0x52…  ？具体内容
2022/10/21
WRITE_RTC";
CM_ SG_ 2415980177 M2P_Response_Byte2_01 "新增功能使用： 功能编码，根据功能定义具含义
2022/10/21
wgw:时间标定状态
";
CM_ SG_ 2415980177 M2P_Response_Byte3_01 "根据功能码定义和解析数据1
2022/10/21
年";
CM_ SG_ 2415980177 M2P_Response_Byte4_01 "根据功能码定义和解析数据2
2022/10/21
月";
CM_ SG_ 2415980177 M2P_Response_Byte5_01 "根据功能码定义和解析数据3
2022/10/21
日";
CM_ SG_ 2415980177 M2P_Response_Byte6_01 "根据功能码定义和解析数据4
2022/10/21
时";
CM_ SG_ 2415980177 M2P_Response_Byte7_01 "根据功能码定义和解析数据5
2022/10/21
分";
CM_ SG_ 2415980177 M2P_Response_Byte8_01 "根据功能码定义和解析数据6
2022/10/21
秒";
CM_ SG_ 2415980178 M2P_Response_Byte1_02 "MBMU给PC的反馈信息1,新增功能使用： 0xA0  反馈写入结果  ，0x50反馈读取结果；
如果需要反馈多报文，使用0x51，0x52…  ？具体内容
2022/10/21
WRITE_RTC";
CM_ SG_ 2415980178 M2P_Response_Byte2_02 "新增功能使用： 功能编码，根据功能定义具含义
2022/10/21
wgw:时间标定状态
";
CM_ SG_ 2415980178 M2P_Response_Byte3_02 "根据功能码定义和解析数据1
2022/10/21
年";
CM_ SG_ 2415980178 M2P_Response_Byte4_02 "根据功能码定义和解析数据2
2022/10/21
月";
CM_ SG_ 2415980178 M2P_Response_Byte5_02 "根据功能码定义和解析数据3
2022/10/21
日";
CM_ SG_ 2415980178 M2P_Response_Byte6_02 "根据功能码定义和解析数据4
2022/10/21
时";
CM_ SG_ 2415980178 M2P_Response_Byte7_02 "根据功能码定义和解析数据5
2022/10/21
分";
CM_ SG_ 2415980178 M2P_Response_Byte8_02 "根据功能码定义和解析数据6
2022/10/21
秒";
CM_ SG_ 2415980179 M2P_Response_Byte1_03 "MBMU给PC的反馈信息1,新增功能使用： 0xA0  反馈写入结果  ，0x50反馈读取结果；
如果需要反馈多报文，使用0x51，0x52…  ？具体内容
2022/10/21
WRITE_RTC";
CM_ SG_ 2415980179 M2P_Response_Byte2_03 "新增功能使用： 功能编码，根据功能定义具含义
2022/10/21
wgw:时间标定状态
";
CM_ SG_ 2415980179 M2P_Response_Byte3_03 "根据功能码定义和解析数据1
2022/10/21
年";
CM_ SG_ 2415980179 M2P_Response_Byte4_03 "根据功能码定义和解析数据2
2022/10/21
月";
CM_ SG_ 2415980179 M2P_Response_Byte5_03 "根据功能码定义和解析数据3
2022/10/21
日";
CM_ SG_ 2415980179 M2P_Response_Byte6_03 "根据功能码定义和解析数据4
2022/10/21
时";
CM_ SG_ 2415980179 M2P_Response_Byte7_03 "根据功能码定义和解析数据5
2022/10/21
分";
CM_ SG_ 2415980179 M2P_Response_Byte8_03 "根据功能码定义和解析数据6
2022/10/21
秒";
CM_ SG_ 2415980180 M2P_Response_Byte1_04 "MBMU给PC的反馈信息1,新增功能使用： 0xA0  反馈写入结果  ，0x50反馈读取结果；
如果需要反馈多报文，使用0x51，0x52…  ？具体内容
2022/10/21
WRITE_RTC";
CM_ SG_ 2415980180 M2P_Response_Byte2_04 "新增功能使用： 功能编码，根据功能定义具含义
2022/10/21
wgw:时间标定状态
";
CM_ SG_ 2415980180 M2P_Response_Byte3_04 "根据功能码定义和解析数据1
2022/10/21
年";
CM_ SG_ 2415980180 M2P_Response_Byte4_04 "根据功能码定义和解析数据2
2022/10/21
月";
CM_ SG_ 2415980180 M2P_Response_Byte5_04 "根据功能码定义和解析数据3
2022/10/21
日";
CM_ SG_ 2415980180 M2P_Response_Byte6_04 "根据功能码定义和解析数据4
2022/10/21
时";
CM_ SG_ 2415980180 M2P_Response_Byte7_04 "根据功能码定义和解析数据5
2022/10/21
分";
CM_ SG_ 2415980180 M2P_Response_Byte8_04 "根据功能码定义和解析数据6
2022/10/21
秒";
CM_ SG_ 2415980181 M2P_Response_Byte1_05 "MBMU给PC的反馈信息1,新增功能使用： 0xA0  反馈写入结果  ，0x50反馈读取结果；
如果需要反馈多报文，使用0x51，0x52…  ？具体内容
2022/10/21
WRITE_RTC";
CM_ SG_ 2415980181 M2P_Response_Byte2_05 "新增功能使用： 功能编码，根据功能定义具含义
2022/10/21
wgw:时间标定状态
";
CM_ SG_ 2415980181 M2P_Response_Byte3_05 "根据功能码定义和解析数据1
2022/10/21
年";
CM_ SG_ 2415980181 M2P_Response_Byte4_05 "根据功能码定义和解析数据2
2022/10/21
月";
CM_ SG_ 2415980181 M2P_Response_Byte5_05 "根据功能码定义和解析数据3
2022/10/21
日";
CM_ SG_ 2415980181 M2P_Response_Byte6_05 "根据功能码定义和解析数据4
2022/10/21
时";
CM_ SG_ 2415980181 M2P_Response_Byte7_05 "根据功能码定义和解析数据5
2022/10/21
分";
CM_ SG_ 2415980181 M2P_Response_Byte8_05 "根据功能码定义和解析数据6
2022/10/21
秒";
CM_ SG_ 2415980182 M2P_Response_Byte1_06 "MBMU给PC的反馈信息1,新增功能使用： 0xA0  反馈写入结果  ，0x50反馈读取结果；
如果需要反馈多报文，使用0x51，0x52…  ？具体内容
2022/10/21
WRITE_RTC";
CM_ SG_ 2415980182 M2P_Response_Byte2_06 "新增功能使用： 功能编码，根据功能定义具含义
2022/10/21
wgw:时间标定状态
";
CM_ SG_ 2415980182 M2P_Response_Byte3_06 "根据功能码定义和解析数据1
2022/10/21
年";
CM_ SG_ 2415980182 M2P_Response_Byte4_06 "根据功能码定义和解析数据2
2022/10/21
月";
CM_ SG_ 2415980182 M2P_Response_Byte5_06 "根据功能码定义和解析数据3
2022/10/21
日";
CM_ SG_ 2415980182 M2P_Response_Byte6_06 "根据功能码定义和解析数据4
2022/10/21
时";
CM_ SG_ 2415980182 M2P_Response_Byte7_06 "根据功能码定义和解析数据5
2022/10/21
分";
CM_ SG_ 2415980182 M2P_Response_Byte8_06 "根据功能码定义和解析数据6
2022/10/21
秒";
CM_ SG_ 2415980183 M2P_Response_Byte1_07 "MBMU给PC的反馈信息1,新增功能使用： 0xA0  反馈写入结果  ，0x50反馈读取结果；
如果需要反馈多报文，使用0x51，0x52…  ？具体内容
2022/10/21
WRITE_RTC";
CM_ SG_ 2415980183 M2P_Response_Byte2_07 "新增功能使用： 功能编码，根据功能定义具含义
2022/10/21
wgw:时间标定状态
";
CM_ SG_ 2415980183 M2P_Response_Byte3_07 "根据功能码定义和解析数据1
2022/10/21
年";
CM_ SG_ 2415980183 M2P_Response_Byte4_07 "根据功能码定义和解析数据2
2022/10/21
月";
CM_ SG_ 2415980183 M2P_Response_Byte5_07 "根据功能码定义和解析数据3
2022/10/21
日";
CM_ SG_ 2415980183 M2P_Response_Byte6_07 "根据功能码定义和解析数据4
2022/10/21
时";
CM_ SG_ 2415980183 M2P_Response_Byte7_07 "根据功能码定义和解析数据5
2022/10/21
分";
CM_ SG_ 2415980183 M2P_Response_Byte8_07 "根据功能码定义和解析数据6
2022/10/21
秒";
CM_ SG_ 2415980184 M2P_Response_Byte1_08 "MBMU给PC的反馈信息1,新增功能使用： 0xA0  反馈写入结果  ，0x50反馈读取结果；
如果需要反馈多报文，使用0x51，0x52…  ？具体内容
2022/10/21
WRITE_RTC";
CM_ SG_ 2415980184 M2P_Response_Byte2_08 "新增功能使用： 功能编码，根据功能定义具含义
2022/10/21
wgw:时间标定状态
";
CM_ SG_ 2415980184 M2P_Response_Byte3_08 "根据功能码定义和解析数据1
2022/10/21
年";
CM_ SG_ 2415980184 M2P_Response_Byte4_08 "根据功能码定义和解析数据2
2022/10/21
月";
CM_ SG_ 2415980184 M2P_Response_Byte5_08 "根据功能码定义和解析数据3
2022/10/21
日";
CM_ SG_ 2415980184 M2P_Response_Byte6_08 "根据功能码定义和解析数据4
2022/10/21
时";
CM_ SG_ 2415980184 M2P_Response_Byte7_08 "根据功能码定义和解析数据5
2022/10/21
分";
CM_ SG_ 2415980184 M2P_Response_Byte8_08 "根据功能码定义和解析数据6
2022/10/21
秒";
CM_ SG_ 2415980185 M2P_Response_Byte1_09 "MBMU给PC的反馈信息1,新增功能使用： 0xA0  反馈写入结果  ，0x50反馈读取结果；
如果需要反馈多报文，使用0x51，0x52…  ？具体内容
2022/10/21
WRITE_RTC";
CM_ SG_ 2415980185 M2P_Response_Byte2_09 "新增功能使用： 功能编码，根据功能定义具含义
2022/10/21
wgw:时间标定状态
";
CM_ SG_ 2415980185 M2P_Response_Byte3_09 "根据功能码定义和解析数据1
2022/10/21
年";
CM_ SG_ 2415980185 M2P_Response_Byte4_09 "根据功能码定义和解析数据2
2022/10/21
月";
CM_ SG_ 2415980185 M2P_Response_Byte5_09 "根据功能码定义和解析数据3
2022/10/21
日";
CM_ SG_ 2415980185 M2P_Response_Byte6_09 "根据功能码定义和解析数据4
2022/10/21
时";
CM_ SG_ 2415980185 M2P_Response_Byte7_09 "根据功能码定义和解析数据5
2022/10/21
分";
CM_ SG_ 2415980185 M2P_Response_Byte8_09 "根据功能码定义和解析数据6
2022/10/21
秒";
CM_ SG_ 2415980186 M2P_Response_Byte1_10 "MBMU给PC的反馈信息1,新增功能使用： 0xA0  反馈写入结果  ，0x50反馈读取结果；
如果需要反馈多报文，使用0x51，0x52…  ？具体内容
2022/10/21
WRITE_RTC";
CM_ SG_ 2415980186 M2P_Response_Byte2_10 "新增功能使用： 功能编码，根据功能定义具含义
2022/10/21
wgw:时间标定状态
";
CM_ SG_ 2415980186 M2P_Response_Byte3_10 "根据功能码定义和解析数据1
2022/10/21
年";
CM_ SG_ 2415980186 M2P_Response_Byte4_10 "根据功能码定义和解析数据2
2022/10/21
月";
CM_ SG_ 2415980186 M2P_Response_Byte5_10 "根据功能码定义和解析数据3
2022/10/21
日";
CM_ SG_ 2415980186 M2P_Response_Byte6_10 "根据功能码定义和解析数据4
2022/10/21
时";
CM_ SG_ 2415980186 M2P_Response_Byte7_10 "根据功能码定义和解析数据5
2022/10/21
分";
CM_ SG_ 2415980186 M2P_Response_Byte8_10 "根据功能码定义和解析数据6
2022/10/21
秒";
CM_ SG_ 2415980187 M2P_Response_Byte1_11 "MBMU给PC的反馈信息1,新增功能使用： 0xA0  反馈写入结果  ，0x50反馈读取结果；
如果需要反馈多报文，使用0x51，0x52…  ？具体内容
2022/10/21
WRITE_RTC";
CM_ SG_ 2415980187 M2P_Response_Byte2_11 "新增功能使用： 功能编码，根据功能定义具含义
2022/10/21
wgw:时间标定状态
";
CM_ SG_ 2415980187 M2P_Response_Byte3_11 "根据功能码定义和解析数据1
2022/10/21
年";
CM_ SG_ 2415980187 M2P_Response_Byte4_11 "根据功能码定义和解析数据2
2022/10/21
月";
CM_ SG_ 2415980187 M2P_Response_Byte5_11 "根据功能码定义和解析数据3
2022/10/21
日";
CM_ SG_ 2415980187 M2P_Response_Byte6_11 "根据功能码定义和解析数据4
2022/10/21
时";
CM_ SG_ 2415980187 M2P_Response_Byte7_11 "根据功能码定义和解析数据5
2022/10/21
分";
CM_ SG_ 2415980187 M2P_Response_Byte8_11 "根据功能码定义和解析数据6
2022/10/21
秒";
CM_ SG_ 2415980188 M2P_Response_Byte1_12 "MBMU给PC的反馈信息1,新增功能使用： 0xA0  反馈写入结果  ，0x50反馈读取结果；
如果需要反馈多报文，使用0x51，0x52…  ？具体内容
2022/10/21
WRITE_RTC";
CM_ SG_ 2415980188 M2P_Response_Byte2_12 "新增功能使用： 功能编码，根据功能定义具含义
2022/10/21
wgw:时间标定状态
";
CM_ SG_ 2415980188 M2P_Response_Byte3_12 "根据功能码定义和解析数据1
2022/10/21
年";
CM_ SG_ 2415980188 M2P_Response_Byte4_12 "根据功能码定义和解析数据2
2022/10/21
月";
CM_ SG_ 2415980188 M2P_Response_Byte5_12 "根据功能码定义和解析数据3
2022/10/21
日";
CM_ SG_ 2415980188 M2P_Response_Byte6_12 "根据功能码定义和解析数据4
2022/10/21
时";
CM_ SG_ 2415980188 M2P_Response_Byte7_12 "根据功能码定义和解析数据5
2022/10/21
分";
CM_ SG_ 2415980188 M2P_Response_Byte8_12 "根据功能码定义和解析数据6
2022/10/21
秒";
CM_ SG_ 2415980189 M2P_Response_Byte1_13 "MBMU给PC的反馈信息1,新增功能使用： 0xA0  反馈写入结果  ，0x50反馈读取结果；
如果需要反馈多报文，使用0x51，0x52…  ？具体内容
2022/10/21
WRITE_RTC";
CM_ SG_ 2415980189 M2P_Response_Byte2_13 "新增功能使用： 功能编码，根据功能定义具含义
2022/10/21
wgw:时间标定状态
";
CM_ SG_ 2415980189 M2P_Response_Byte3_13 "根据功能码定义和解析数据1
2022/10/21
年";
CM_ SG_ 2415980189 M2P_Response_Byte4_13 "根据功能码定义和解析数据2
2022/10/21
月";
CM_ SG_ 2415980189 M2P_Response_Byte5_13 "根据功能码定义和解析数据3
2022/10/21
日";
CM_ SG_ 2415980189 M2P_Response_Byte6_13 "根据功能码定义和解析数据4
2022/10/21
时";
CM_ SG_ 2415980189 M2P_Response_Byte7_13 "根据功能码定义和解析数据5
2022/10/21
分";
CM_ SG_ 2415980189 M2P_Response_Byte8_13 "根据功能码定义和解析数据6
2022/10/21
秒";
CM_ SG_ 2415980190 M2P_Response_Byte1_14 "MBMU给PC的反馈信息1,新增功能使用： 0xA0  反馈写入结果  ，0x50反馈读取结果；
如果需要反馈多报文，使用0x51，0x52…  ？具体内容
2022/10/21
WRITE_RTC";
CM_ SG_ 2415980190 M2P_Response_Byte2_14 "新增功能使用： 功能编码，根据功能定义具含义
2022/10/21
wgw:时间标定状态
";
CM_ SG_ 2415980190 M2P_Response_Byte3_14 "根据功能码定义和解析数据1
2022/10/21
年";
CM_ SG_ 2415980190 M2P_Response_Byte4_14 "根据功能码定义和解析数据2
2022/10/21
月";
CM_ SG_ 2415980190 M2P_Response_Byte5_14 "根据功能码定义和解析数据3
2022/10/21
日";
CM_ SG_ 2415980190 M2P_Response_Byte6_14 "根据功能码定义和解析数据4
2022/10/21
时";
CM_ SG_ 2415980190 M2P_Response_Byte7_14 "根据功能码定义和解析数据5
2022/10/21
分";
CM_ SG_ 2415980190 M2P_Response_Byte8_14 "根据功能码定义和解析数据6
2022/10/21
秒";
CM_ SG_ 2415980191 M2P_Response_Byte1_15 "MBMU给PC的反馈信息1,新增功能使用： 0xA0  反馈写入结果  ，0x50反馈读取结果；
如果需要反馈多报文，使用0x51，0x52…  ？具体内容
2022/10/21
WRITE_RTC";
CM_ SG_ 2415980191 M2P_Response_Byte2_15 "新增功能使用： 功能编码，根据功能定义具含义
2022/10/21
wgw:时间标定状态
";
CM_ SG_ 2415980191 M2P_Response_Byte3_15 "根据功能码定义和解析数据1
2022/10/21
年";
CM_ SG_ 2415980191 M2P_Response_Byte4_15 "根据功能码定义和解析数据2
2022/10/21
月";
CM_ SG_ 2415980191 M2P_Response_Byte5_15 "根据功能码定义和解析数据3
2022/10/21
日";
CM_ SG_ 2415980191 M2P_Response_Byte6_15 "根据功能码定义和解析数据4
2022/10/21
时";
CM_ SG_ 2415980191 M2P_Response_Byte7_15 "根据功能码定义和解析数据5
2022/10/21
分";
CM_ SG_ 2415980191 M2P_Response_Byte8_15 "根据功能码定义和解析数据6
2022/10/21
秒";
CM_ SG_ 2415980192 M2P_Response_Byte1_16 "MBMU给PC的反馈信息1,新增功能使用： 0xA0  反馈写入结果  ，0x50反馈读取结果；
如果需要反馈多报文，使用0x51，0x52…  ？具体内容
2022/10/21
WRITE_RTC";
CM_ SG_ 2415980192 M2P_Response_Byte2_16 "新增功能使用： 功能编码，根据功能定义具含义
2022/10/21
wgw:时间标定状态
";
CM_ SG_ 2415980192 M2P_Response_Byte3_16 "根据功能码定义和解析数据1
2022/10/21
年";
CM_ SG_ 2415980192 M2P_Response_Byte4_16 "根据功能码定义和解析数据2
2022/10/21
月";
CM_ SG_ 2415980192 M2P_Response_Byte5_16 "根据功能码定义和解析数据3
2022/10/21
日";
CM_ SG_ 2415980192 M2P_Response_Byte6_16 "根据功能码定义和解析数据4
2022/10/21
时";
CM_ SG_ 2415980192 M2P_Response_Byte7_16 "根据功能码定义和解析数据5
2022/10/21
分";
CM_ SG_ 2415980192 M2P_Response_Byte8_16 "根据功能码定义和解析数据6
2022/10/21
秒";
CM_ SG_ 2415980193 M2P_Response_Byte1_17 "MBMU给PC的反馈信息1,新增功能使用： 0xA0  反馈写入结果  ，0x50反馈读取结果；
如果需要反馈多报文，使用0x51，0x52…  ？具体内容
2022/10/21
WRITE_RTC";
CM_ SG_ 2415980193 M2P_Response_Byte2_17 "新增功能使用： 功能编码，根据功能定义具含义
2022/10/21
wgw:时间标定状态
";
CM_ SG_ 2415980193 M2P_Response_Byte3_17 "根据功能码定义和解析数据1
2022/10/21
年";
CM_ SG_ 2415980193 M2P_Response_Byte4_17 "根据功能码定义和解析数据2
2022/10/21
月";
CM_ SG_ 2415980193 M2P_Response_Byte5_17 "根据功能码定义和解析数据3
2022/10/21
日";
CM_ SG_ 2415980193 M2P_Response_Byte6_17 "根据功能码定义和解析数据4
2022/10/21
时";
CM_ SG_ 2415980193 M2P_Response_Byte7_17 "根据功能码定义和解析数据5
2022/10/21
分";
CM_ SG_ 2415980193 M2P_Response_Byte8_17 "根据功能码定义和解析数据6
2022/10/21
秒";
CM_ SG_ 2415980194 M2P_Response_Byte1_18 "MBMU给PC的反馈信息1,新增功能使用： 0xA0  反馈写入结果  ，0x50反馈读取结果；
如果需要反馈多报文，使用0x51，0x52…  ？具体内容
2022/10/21
WRITE_RTC";
CM_ SG_ 2415980194 M2P_Response_Byte2_18 "新增功能使用： 功能编码，根据功能定义具含义
2022/10/21
wgw:时间标定状态
";
CM_ SG_ 2415980194 M2P_Response_Byte3_18 "根据功能码定义和解析数据1
2022/10/21
年";
CM_ SG_ 2415980194 M2P_Response_Byte4_18 "根据功能码定义和解析数据2
2022/10/21
月";
CM_ SG_ 2415980194 M2P_Response_Byte5_18 "根据功能码定义和解析数据3
2022/10/21
日";
CM_ SG_ 2415980194 M2P_Response_Byte6_18 "根据功能码定义和解析数据4
2022/10/21
时";
CM_ SG_ 2415980194 M2P_Response_Byte7_18 "根据功能码定义和解析数据5
2022/10/21
分";
CM_ SG_ 2415980194 M2P_Response_Byte8_18 "根据功能码定义和解析数据6
2022/10/21
秒";
CM_ SG_ 2415980195 M2P_Response_Byte1_19 "MBMU给PC的反馈信息1,新增功能使用： 0xA0  反馈写入结果  ，0x50反馈读取结果；
如果需要反馈多报文，使用0x51，0x52…  ？具体内容
2022/10/21
WRITE_RTC";
CM_ SG_ 2415980195 M2P_Response_Byte2_19 "新增功能使用： 功能编码，根据功能定义具含义
2022/10/21
wgw:时间标定状态
";
CM_ SG_ 2415980195 M2P_Response_Byte3_19 "根据功能码定义和解析数据1
2022/10/21
年";
CM_ SG_ 2415980195 M2P_Response_Byte4_19 "根据功能码定义和解析数据2
2022/10/21
月";
CM_ SG_ 2415980195 M2P_Response_Byte5_19 "根据功能码定义和解析数据3
2022/10/21
日";
CM_ SG_ 2415980195 M2P_Response_Byte6_19 "根据功能码定义和解析数据4
2022/10/21
时";
CM_ SG_ 2415980195 M2P_Response_Byte7_19 "根据功能码定义和解析数据5
2022/10/21
分";
CM_ SG_ 2415980195 M2P_Response_Byte8_19 "根据功能码定义和解析数据6
2022/10/21
秒";
CM_ SG_ 2415980196 M2P_Response_Byte1_20 "MBMU给PC的反馈信息1,新增功能使用： 0xA0  反馈写入结果  ，0x50反馈读取结果；
如果需要反馈多报文，使用0x51，0x52…  ？具体内容
2022/10/21
WRITE_RTC";
CM_ SG_ 2415980196 M2P_Response_Byte2_20 "新增功能使用： 功能编码，根据功能定义具含义
2022/10/21
wgw:时间标定状态
";
CM_ SG_ 2415980196 M2P_Response_Byte3_20 "根据功能码定义和解析数据1
2022/10/21
年";
CM_ SG_ 2415980196 M2P_Response_Byte4_20 "根据功能码定义和解析数据2
2022/10/21
月";
CM_ SG_ 2415980196 M2P_Response_Byte5_20 "根据功能码定义和解析数据3
2022/10/21
日";
CM_ SG_ 2415980196 M2P_Response_Byte6_20 "根据功能码定义和解析数据4
2022/10/21
时";
CM_ SG_ 2415980196 M2P_Response_Byte7_20 "根据功能码定义和解析数据5
2022/10/21
分";
CM_ SG_ 2415980196 M2P_Response_Byte8_20 "根据功能码定义和解析数据6
2022/10/21
秒";
CM_ SG_ 2415980197 M2P_Response_Byte1_21 "MBMU给PC的反馈信息1,新增功能使用： 0xA0  反馈写入结果  ，0x50反馈读取结果；
如果需要反馈多报文，使用0x51，0x52…  ？具体内容
2022/10/21
WRITE_RTC";
CM_ SG_ 2415980197 M2P_Response_Byte2_21 "新增功能使用： 功能编码，根据功能定义具含义
2022/10/21
wgw:时间标定状态
";
CM_ SG_ 2415980197 M2P_Response_Byte3_21 "根据功能码定义和解析数据1
2022/10/21
年";
CM_ SG_ 2415980197 M2P_Response_Byte4_21 "根据功能码定义和解析数据2
2022/10/21
月";
CM_ SG_ 2415980197 M2P_Response_Byte5_21 "根据功能码定义和解析数据3
2022/10/21
日";
CM_ SG_ 2415980197 M2P_Response_Byte6_21 "根据功能码定义和解析数据4
2022/10/21
时";
CM_ SG_ 2415980197 M2P_Response_Byte7_21 "根据功能码定义和解析数据5
2022/10/21
分";
CM_ SG_ 2415980197 M2P_Response_Byte8_21 "根据功能码定义和解析数据6
2022/10/21
秒";
CM_ SG_ 2415980198 M2P_Response_Byte1_22 "MBMU给PC的反馈信息1,新增功能使用： 0xA0  反馈写入结果  ，0x50反馈读取结果；
如果需要反馈多报文，使用0x51，0x52…  ？具体内容
2022/10/21
WRITE_RTC";
CM_ SG_ 2415980198 M2P_Response_Byte2_22 "新增功能使用： 功能编码，根据功能定义具含义
2022/10/21
wgw:时间标定状态
";
CM_ SG_ 2415980198 M2P_Response_Byte3_22 "根据功能码定义和解析数据1
2022/10/21
年";
CM_ SG_ 2415980198 M2P_Response_Byte4_22 "根据功能码定义和解析数据2
2022/10/21
月";
CM_ SG_ 2415980198 M2P_Response_Byte5_22 "根据功能码定义和解析数据3
2022/10/21
日";
CM_ SG_ 2415980198 M2P_Response_Byte6_22 "根据功能码定义和解析数据4
2022/10/21
时";
CM_ SG_ 2415980198 M2P_Response_Byte7_22 "根据功能码定义和解析数据5
2022/10/21
分";
CM_ SG_ 2415980198 M2P_Response_Byte8_22 "根据功能码定义和解析数据6
2022/10/21
秒";
CM_ SG_ 2415980199 M2P_Response_Byte1_23 "MBMU给PC的反馈信息1,新增功能使用： 0xA0  反馈写入结果  ，0x50反馈读取结果；
如果需要反馈多报文，使用0x51，0x52…  ？具体内容
2022/10/21
WRITE_RTC";
CM_ SG_ 2415980199 M2P_Response_Byte2_23 "新增功能使用： 功能编码，根据功能定义具含义
2022/10/21
wgw:时间标定状态
";
CM_ SG_ 2415980199 M2P_Response_Byte3_23 "根据功能码定义和解析数据1
2022/10/21
年";
CM_ SG_ 2415980199 M2P_Response_Byte4_23 "根据功能码定义和解析数据2
2022/10/21
月";
CM_ SG_ 2415980199 M2P_Response_Byte5_23 "根据功能码定义和解析数据3
2022/10/21
日";
CM_ SG_ 2415980199 M2P_Response_Byte6_23 "根据功能码定义和解析数据4
2022/10/21
时";
CM_ SG_ 2415980199 M2P_Response_Byte7_23 "根据功能码定义和解析数据5
2022/10/21
分";
CM_ SG_ 2415980199 M2P_Response_Byte8_23 "根据功能码定义和解析数据6
2022/10/21
秒";
CM_ SG_ 2415980200 M2P_Response_Byte1_24 "MBMU给PC的反馈信息1,新增功能使用： 0xA0  反馈写入结果  ，0x50反馈读取结果；
如果需要反馈多报文，使用0x51，0x52…  ？具体内容
2022/10/21
WRITE_RTC";
CM_ SG_ 2415980200 M2P_Response_Byte2_24 "新增功能使用： 功能编码，根据功能定义具含义
2022/10/21
wgw:时间标定状态
";
CM_ SG_ 2415980200 M2P_Response_Byte3_24 "根据功能码定义和解析数据1
2022/10/21
年";
CM_ SG_ 2415980200 M2P_Response_Byte4_24 "根据功能码定义和解析数据2
2022/10/21
月";
CM_ SG_ 2415980200 M2P_Response_Byte5_24 "根据功能码定义和解析数据3
2022/10/21
日";
CM_ SG_ 2415980200 M2P_Response_Byte6_24 "根据功能码定义和解析数据4
2022/10/21
时";
CM_ SG_ 2415980200 M2P_Response_Byte7_24 "根据功能码定义和解析数据5
2022/10/21
分";
CM_ SG_ 2415980200 M2P_Response_Byte8_24 "根据功能码定义和解析数据6
2022/10/21
秒";
CM_ SG_ 2415980201 M2P_Response_Byte1_25 "MBMU给PC的反馈信息1,新增功能使用： 0xA0  反馈写入结果  ，0x50反馈读取结果；
如果需要反馈多报文，使用0x51，0x52…  ？具体内容
2022/10/21
WRITE_RTC";
CM_ SG_ 2415980201 M2P_Response_Byte2_25 "新增功能使用： 功能编码，根据功能定义具含义
2022/10/21
wgw:时间标定状态
";
CM_ SG_ 2415980201 M2P_Response_Byte3_25 "根据功能码定义和解析数据1
2022/10/21
年";
CM_ SG_ 2415980201 M2P_Response_Byte4_25 "根据功能码定义和解析数据2
2022/10/21
月";
CM_ SG_ 2415980201 M2P_Response_Byte5_25 "根据功能码定义和解析数据3
2022/10/21
日";
CM_ SG_ 2415980201 M2P_Response_Byte6_25 "根据功能码定义和解析数据4
2022/10/21
时";
CM_ SG_ 2415980201 M2P_Response_Byte7_25 "根据功能码定义和解析数据5
2022/10/21
分";
CM_ SG_ 2415980201 M2P_Response_Byte8_25 "根据功能码定义和解析数据6
2022/10/21
秒";
CM_ SG_ 2415980202 M2P_Response_Byte1_26 "MBMU给PC的反馈信息1,新增功能使用： 0xA0  反馈写入结果  ，0x50反馈读取结果；
如果需要反馈多报文，使用0x51，0x52…  ？具体内容
2022/10/21
WRITE_RTC";
CM_ SG_ 2415980202 M2P_Response_Byte2_26 "新增功能使用： 功能编码，根据功能定义具含义
2022/10/21
wgw:时间标定状态
";
CM_ SG_ 2415980202 M2P_Response_Byte3_26 "根据功能码定义和解析数据1
2022/10/21
年";
CM_ SG_ 2415980202 M2P_Response_Byte4_26 "根据功能码定义和解析数据2
2022/10/21
月";
CM_ SG_ 2415980202 M2P_Response_Byte5_26 "根据功能码定义和解析数据3
2022/10/21
日";
CM_ SG_ 2415980202 M2P_Response_Byte6_26 "根据功能码定义和解析数据4
2022/10/21
时";
CM_ SG_ 2415980202 M2P_Response_Byte7_26 "根据功能码定义和解析数据5
2022/10/21
分";
CM_ SG_ 2415980202 M2P_Response_Byte8_26 "根据功能码定义和解析数据6
2022/10/21
秒";
CM_ SG_ 2415980203 M2P_Response_Byte1_27 "MBMU给PC的反馈信息1,新增功能使用： 0xA0  反馈写入结果  ，0x50反馈读取结果；
如果需要反馈多报文，使用0x51，0x52…  ？具体内容
2022/10/21
WRITE_RTC";
CM_ SG_ 2415980203 M2P_Response_Byte2_27 "新增功能使用： 功能编码，根据功能定义具含义
2022/10/21
wgw:时间标定状态
";
CM_ SG_ 2415980203 M2P_Response_Byte3_27 "根据功能码定义和解析数据1
2022/10/21
年";
CM_ SG_ 2415980203 M2P_Response_Byte4_27 "根据功能码定义和解析数据2
2022/10/21
月";
CM_ SG_ 2415980203 M2P_Response_Byte5_27 "根据功能码定义和解析数据3
2022/10/21
日";
CM_ SG_ 2415980203 M2P_Response_Byte6_27 "根据功能码定义和解析数据4
2022/10/21
时";
CM_ SG_ 2415980203 M2P_Response_Byte7_27 "根据功能码定义和解析数据5
2022/10/21
分";
CM_ SG_ 2415980203 M2P_Response_Byte8_27 "根据功能码定义和解析数据6
2022/10/21
秒";
CM_ SG_ 2415980204 M2P_Response_Byte1_28 "MBMU给PC的反馈信息1,新增功能使用： 0xA0  反馈写入结果  ，0x50反馈读取结果；
如果需要反馈多报文，使用0x51，0x52…  ？具体内容
2022/10/21
WRITE_RTC";
CM_ SG_ 2415980204 M2P_Response_Byte2_28 "新增功能使用： 功能编码，根据功能定义具含义
2022/10/21
wgw:时间标定状态
";
CM_ SG_ 2415980204 M2P_Response_Byte3_28 "根据功能码定义和解析数据1
2022/10/21
年";
CM_ SG_ 2415980204 M2P_Response_Byte4_28 "根据功能码定义和解析数据2
2022/10/21
月";
CM_ SG_ 2415980204 M2P_Response_Byte5_28 "根据功能码定义和解析数据3
2022/10/21
日";
CM_ SG_ 2415980204 M2P_Response_Byte6_28 "根据功能码定义和解析数据4
2022/10/21
时";
CM_ SG_ 2415980204 M2P_Response_Byte7_28 "根据功能码定义和解析数据5
2022/10/21
分";
CM_ SG_ 2415980204 M2P_Response_Byte8_28 "根据功能码定义和解析数据6
2022/10/21
秒";
CM_ SG_ 2415980205 M2P_Response_Byte1_29 "MBMU给PC的反馈信息1,新增功能使用： 0xA0  反馈写入结果  ，0x50反馈读取结果；
如果需要反馈多报文，使用0x51，0x52…  ？具体内容
2022/10/21
WRITE_RTC";
CM_ SG_ 2415980205 M2P_Response_Byte2_29 "新增功能使用： 功能编码，根据功能定义具含义
2022/10/21
wgw:时间标定状态
";
CM_ SG_ 2415980205 M2P_Response_Byte3_29 "根据功能码定义和解析数据1
2022/10/21
年";
CM_ SG_ 2415980205 M2P_Response_Byte4_29 "根据功能码定义和解析数据2
2022/10/21
月";
CM_ SG_ 2415980205 M2P_Response_Byte5_29 "根据功能码定义和解析数据3
2022/10/21
日";
CM_ SG_ 2415980205 M2P_Response_Byte6_29 "根据功能码定义和解析数据4
2022/10/21
时";
CM_ SG_ 2415980205 M2P_Response_Byte7_29 "根据功能码定义和解析数据5
2022/10/21
分";
CM_ SG_ 2415980205 M2P_Response_Byte8_29 "根据功能码定义和解析数据6
2022/10/21
秒";
CM_ SG_ 2415980206 M2P_Response_Byte1_30 "MBMU给PC的反馈信息1,新增功能使用： 0xA0  反馈写入结果  ，0x50反馈读取结果；
如果需要反馈多报文，使用0x51，0x52…  ？具体内容
2022/10/21
WRITE_RTC";
CM_ SG_ 2415980206 M2P_Response_Byte2_30 "新增功能使用： 功能编码，根据功能定义具含义
2022/10/21
wgw:时间标定状态
";
CM_ SG_ 2415980206 M2P_Response_Byte3_30 "根据功能码定义和解析数据1
2022/10/21
年";
CM_ SG_ 2415980206 M2P_Response_Byte4_30 "根据功能码定义和解析数据2
2022/10/21
月";
CM_ SG_ 2415980206 M2P_Response_Byte5_30 "根据功能码定义和解析数据3
2022/10/21
日";
CM_ SG_ 2415980206 M2P_Response_Byte6_30 "根据功能码定义和解析数据4
2022/10/21
时";
CM_ SG_ 2415980206 M2P_Response_Byte7_30 "根据功能码定义和解析数据5
2022/10/21
分";
CM_ SG_ 2415980206 M2P_Response_Byte8_30 "根据功能码定义和解析数据6
2022/10/21
秒";
CM_ SG_ 2415980207 M2P_Response_Byte1_31 "MBMU给PC的反馈信息1,新增功能使用： 0xA0  反馈写入结果  ，0x50反馈读取结果；
如果需要反馈多报文，使用0x51，0x52…  ？具体内容
2022/10/21
WRITE_RTC";
CM_ SG_ 2415980207 M2P_Response_Byte2_31 "新增功能使用： 功能编码，根据功能定义具含义
2022/10/21
wgw:时间标定状态
";
CM_ SG_ 2415980207 M2P_Response_Byte3_31 "根据功能码定义和解析数据1
2022/10/21
年";
CM_ SG_ 2415980207 M2P_Response_Byte4_31 "根据功能码定义和解析数据2
2022/10/21
月";
CM_ SG_ 2415980207 M2P_Response_Byte5_31 "根据功能码定义和解析数据3
2022/10/21
日";
CM_ SG_ 2415980207 M2P_Response_Byte6_31 "根据功能码定义和解析数据4
2022/10/21
时";
CM_ SG_ 2415980207 M2P_Response_Byte7_31 "根据功能码定义和解析数据5
2022/10/21
分";
CM_ SG_ 2415980207 M2P_Response_Byte8_31 "根据功能码定义和解析数据6
2022/10/21
秒";
CM_ SG_ 2416045713 M2P_DIAG_BYTE1_01 "MBMU给PC的诊断报文字节1";
CM_ SG_ 2416045713 M2P_DIAG_BYTE2_01 "MBMU给PC的诊断报文字节2";
CM_ SG_ 2416045713 M2P_DIAG_BYTE3_01 "MBMU给PC的诊断报文字节3";
CM_ SG_ 2416045713 M2P_DIAG_BYTE4_01 "MBMU给PC的诊断报文字节4";
CM_ SG_ 2416045713 M2P_DIAG_BYTE5_01 "MBMU给PC的诊断报文字节5";
CM_ SG_ 2416045713 M2P_DIAG_BYTE6_01 "MBMU给PC的诊断报文字节6";
CM_ SG_ 2416045713 M2P_DIAG_BYTE7_01 "MBMU给PC的诊断报文字节7";
CM_ SG_ 2416045713 M2P_DIAG_BYTE8_01 "MBMU给PC的诊断报文字节8";
CM_ SG_ 2416045714 M2P_DIAG_BYTE1_02 "MBMU给PC的诊断报文字节1";
CM_ SG_ 2416045714 M2P_DIAG_BYTE2_02 "MBMU给PC的诊断报文字节2";
CM_ SG_ 2416045714 M2P_DIAG_BYTE3_02 "MBMU给PC的诊断报文字节3";
CM_ SG_ 2416045714 M2P_DIAG_BYTE4_02 "MBMU给PC的诊断报文字节4";
CM_ SG_ 2416045714 M2P_DIAG_BYTE5_02 "MBMU给PC的诊断报文字节5";
CM_ SG_ 2416045714 M2P_DIAG_BYTE6_02 "MBMU给PC的诊断报文字节6";
CM_ SG_ 2416045714 M2P_DIAG_BYTE7_02 "MBMU给PC的诊断报文字节7";
CM_ SG_ 2416045714 M2P_DIAG_BYTE8_02 "MBMU给PC的诊断报文字节8";
CM_ SG_ 2416045715 M2P_DIAG_BYTE1_03 "MBMU给PC的诊断报文字节1";
CM_ SG_ 2416045715 M2P_DIAG_BYTE2_03 "MBMU给PC的诊断报文字节2";
CM_ SG_ 2416045715 M2P_DIAG_BYTE3_03 "MBMU给PC的诊断报文字节3";
CM_ SG_ 2416045715 M2P_DIAG_BYTE4_03 "MBMU给PC的诊断报文字节4";
CM_ SG_ 2416045715 M2P_DIAG_BYTE5_03 "MBMU给PC的诊断报文字节5";
CM_ SG_ 2416045715 M2P_DIAG_BYTE6_03 "MBMU给PC的诊断报文字节6";
CM_ SG_ 2416045715 M2P_DIAG_BYTE7_03 "MBMU给PC的诊断报文字节7";
CM_ SG_ 2416045715 M2P_DIAG_BYTE8_03 "MBMU给PC的诊断报文字节8";
CM_ SG_ 2416045716 M2P_DIAG_BYTE1_04 "MBMU给PC的诊断报文字节1";
CM_ SG_ 2416045716 M2P_DIAG_BYTE2_04 "MBMU给PC的诊断报文字节2";
CM_ SG_ 2416045716 M2P_DIAG_BYTE3_04 "MBMU给PC的诊断报文字节3";
CM_ SG_ 2416045716 M2P_DIAG_BYTE4_04 "MBMU给PC的诊断报文字节4";
CM_ SG_ 2416045716 M2P_DIAG_BYTE5_04 "MBMU给PC的诊断报文字节5";
CM_ SG_ 2416045716 M2P_DIAG_BYTE6_04 "MBMU给PC的诊断报文字节6";
CM_ SG_ 2416045716 M2P_DIAG_BYTE7_04 "MBMU给PC的诊断报文字节7";
CM_ SG_ 2416045716 M2P_DIAG_BYTE8_04 "MBMU给PC的诊断报文字节8";
CM_ SG_ 2416045717 M2P_DIAG_BYTE1_05 "MBMU给PC的诊断报文字节1";
CM_ SG_ 2416045717 M2P_DIAG_BYTE2_05 "MBMU给PC的诊断报文字节2";
CM_ SG_ 2416045717 M2P_DIAG_BYTE3_05 "MBMU给PC的诊断报文字节3";
CM_ SG_ 2416045717 M2P_DIAG_BYTE4_05 "MBMU给PC的诊断报文字节4";
CM_ SG_ 2416045717 M2P_DIAG_BYTE5_05 "MBMU给PC的诊断报文字节5";
CM_ SG_ 2416045717 M2P_DIAG_BYTE6_05 "MBMU给PC的诊断报文字节6";
CM_ SG_ 2416045717 M2P_DIAG_BYTE7_05 "MBMU给PC的诊断报文字节7";
CM_ SG_ 2416045717 M2P_DIAG_BYTE8_05 "MBMU给PC的诊断报文字节8";
CM_ SG_ 2416045718 M2P_DIAG_BYTE1_06 "MBMU给PC的诊断报文字节1";
CM_ SG_ 2416045718 M2P_DIAG_BYTE2_06 "MBMU给PC的诊断报文字节2";
CM_ SG_ 2416045718 M2P_DIAG_BYTE3_06 "MBMU给PC的诊断报文字节3";
CM_ SG_ 2416045718 M2P_DIAG_BYTE4_06 "MBMU给PC的诊断报文字节4";
CM_ SG_ 2416045718 M2P_DIAG_BYTE5_06 "MBMU给PC的诊断报文字节5";
CM_ SG_ 2416045718 M2P_DIAG_BYTE6_06 "MBMU给PC的诊断报文字节6";
CM_ SG_ 2416045718 M2P_DIAG_BYTE7_06 "MBMU给PC的诊断报文字节7";
CM_ SG_ 2416045718 M2P_DIAG_BYTE8_06 "MBMU给PC的诊断报文字节8";
CM_ SG_ 2416045719 M2P_DIAG_BYTE1_07 "MBMU给PC的诊断报文字节1";
CM_ SG_ 2416045719 M2P_DIAG_BYTE2_07 "MBMU给PC的诊断报文字节2";
CM_ SG_ 2416045719 M2P_DIAG_BYTE3_07 "MBMU给PC的诊断报文字节3";
CM_ SG_ 2416045719 M2P_DIAG_BYTE4_07 "MBMU给PC的诊断报文字节4";
CM_ SG_ 2416045719 M2P_DIAG_BYTE5_07 "MBMU给PC的诊断报文字节5";
CM_ SG_ 2416045719 M2P_DIAG_BYTE6_07 "MBMU给PC的诊断报文字节6";
CM_ SG_ 2416045719 M2P_DIAG_BYTE7_07 "MBMU给PC的诊断报文字节7";
CM_ SG_ 2416045719 M2P_DIAG_BYTE8_07 "MBMU给PC的诊断报文字节8";
CM_ SG_ 2416045720 M2P_DIAG_BYTE1_08 "MBMU给PC的诊断报文字节1";
CM_ SG_ 2416045720 M2P_DIAG_BYTE2_08 "MBMU给PC的诊断报文字节2";
CM_ SG_ 2416045720 M2P_DIAG_BYTE3_08 "MBMU给PC的诊断报文字节3";
CM_ SG_ 2416045720 M2P_DIAG_BYTE4_08 "MBMU给PC的诊断报文字节4";
CM_ SG_ 2416045720 M2P_DIAG_BYTE5_08 "MBMU给PC的诊断报文字节5";
CM_ SG_ 2416045720 M2P_DIAG_BYTE6_08 "MBMU给PC的诊断报文字节6";
CM_ SG_ 2416045720 M2P_DIAG_BYTE7_08 "MBMU给PC的诊断报文字节7";
CM_ SG_ 2416045720 M2P_DIAG_BYTE8_08 "MBMU给PC的诊断报文字节8";
CM_ SG_ 2416045721 M2P_DIAG_BYTE1_09 "MBMU给PC的诊断报文字节1";
CM_ SG_ 2416045721 M2P_DIAG_BYTE2_09 "MBMU给PC的诊断报文字节2";
CM_ SG_ 2416045721 M2P_DIAG_BYTE3_09 "MBMU给PC的诊断报文字节3";
CM_ SG_ 2416045721 M2P_DIAG_BYTE4_09 "MBMU给PC的诊断报文字节4";
CM_ SG_ 2416045721 M2P_DIAG_BYTE5_09 "MBMU给PC的诊断报文字节5";
CM_ SG_ 2416045721 M2P_DIAG_BYTE6_09 "MBMU给PC的诊断报文字节6";
CM_ SG_ 2416045721 M2P_DIAG_BYTE7_09 "MBMU给PC的诊断报文字节7";
CM_ SG_ 2416045721 M2P_DIAG_BYTE8_09 "MBMU给PC的诊断报文字节8";
CM_ SG_ 2416045722 M2P_DIAG_BYTE1_10 "MBMU给PC的诊断报文字节1";
CM_ SG_ 2416045722 M2P_DIAG_BYTE2_10 "MBMU给PC的诊断报文字节2";
CM_ SG_ 2416045722 M2P_DIAG_BYTE3_10 "MBMU给PC的诊断报文字节3";
CM_ SG_ 2416045722 M2P_DIAG_BYTE4_10 "MBMU给PC的诊断报文字节4";
CM_ SG_ 2416045722 M2P_DIAG_BYTE5_10 "MBMU给PC的诊断报文字节5";
CM_ SG_ 2416045722 M2P_DIAG_BYTE6_10 "MBMU给PC的诊断报文字节6";
CM_ SG_ 2416045722 M2P_DIAG_BYTE7_10 "MBMU给PC的诊断报文字节7";
CM_ SG_ 2416045722 M2P_DIAG_BYTE8_10 "MBMU给PC的诊断报文字节8";
CM_ SG_ 2416045723 M2P_DIAG_BYTE1_11 "MBMU给PC的诊断报文字节1";
CM_ SG_ 2416045723 M2P_DIAG_BYTE2_11 "MBMU给PC的诊断报文字节2";
CM_ SG_ 2416045723 M2P_DIAG_BYTE3_11 "MBMU给PC的诊断报文字节3";
CM_ SG_ 2416045723 M2P_DIAG_BYTE4_11 "MBMU给PC的诊断报文字节4";
CM_ SG_ 2416045723 M2P_DIAG_BYTE5_11 "MBMU给PC的诊断报文字节5";
CM_ SG_ 2416045723 M2P_DIAG_BYTE6_11 "MBMU给PC的诊断报文字节6";
CM_ SG_ 2416045723 M2P_DIAG_BYTE7_11 "MBMU给PC的诊断报文字节7";
CM_ SG_ 2416045723 M2P_DIAG_BYTE8_11 "MBMU给PC的诊断报文字节8";
CM_ SG_ 2416045724 M2P_DIAG_BYTE1_12 "MBMU给PC的诊断报文字节1";
CM_ SG_ 2416045724 M2P_DIAG_BYTE2_12 "MBMU给PC的诊断报文字节2";
CM_ SG_ 2416045724 M2P_DIAG_BYTE3_12 "MBMU给PC的诊断报文字节3";
CM_ SG_ 2416045724 M2P_DIAG_BYTE4_12 "MBMU给PC的诊断报文字节4";
CM_ SG_ 2416045724 M2P_DIAG_BYTE5_12 "MBMU给PC的诊断报文字节5";
CM_ SG_ 2416045724 M2P_DIAG_BYTE6_12 "MBMU给PC的诊断报文字节6";
CM_ SG_ 2416045724 M2P_DIAG_BYTE7_12 "MBMU给PC的诊断报文字节7";
CM_ SG_ 2416045724 M2P_DIAG_BYTE8_12 "MBMU给PC的诊断报文字节8";
CM_ SG_ 2416045725 M2P_DIAG_BYTE1_13 "MBMU给PC的诊断报文字节1";
CM_ SG_ 2416045725 M2P_DIAG_BYTE2_13 "MBMU给PC的诊断报文字节2";
CM_ SG_ 2416045725 M2P_DIAG_BYTE3_13 "MBMU给PC的诊断报文字节3";
CM_ SG_ 2416045725 M2P_DIAG_BYTE4_13 "MBMU给PC的诊断报文字节4";
CM_ SG_ 2416045725 M2P_DIAG_BYTE5_13 "MBMU给PC的诊断报文字节5";
CM_ SG_ 2416045725 M2P_DIAG_BYTE6_13 "MBMU给PC的诊断报文字节6";
CM_ SG_ 2416045725 M2P_DIAG_BYTE7_13 "MBMU给PC的诊断报文字节7";
CM_ SG_ 2416045725 M2P_DIAG_BYTE8_13 "MBMU给PC的诊断报文字节8";
CM_ SG_ 2416045726 M2P_DIAG_BYTE1_14 "MBMU给PC的诊断报文字节1";
CM_ SG_ 2416045726 M2P_DIAG_BYTE2_14 "MBMU给PC的诊断报文字节2";
CM_ SG_ 2416045726 M2P_DIAG_BYTE3_14 "MBMU给PC的诊断报文字节3";
CM_ SG_ 2416045726 M2P_DIAG_BYTE4_14 "MBMU给PC的诊断报文字节4";
CM_ SG_ 2416045726 M2P_DIAG_BYTE5_14 "MBMU给PC的诊断报文字节5";
CM_ SG_ 2416045726 M2P_DIAG_BYTE6_14 "MBMU给PC的诊断报文字节6";
CM_ SG_ 2416045726 M2P_DIAG_BYTE7_14 "MBMU给PC的诊断报文字节7";
CM_ SG_ 2416045726 M2P_DIAG_BYTE8_14 "MBMU给PC的诊断报文字节8";
CM_ SG_ 2416045727 M2P_DIAG_BYTE1_15 "MBMU给PC的诊断报文字节1";
CM_ SG_ 2416045727 M2P_DIAG_BYTE2_15 "MBMU给PC的诊断报文字节2";
CM_ SG_ 2416045727 M2P_DIAG_BYTE3_15 "MBMU给PC的诊断报文字节3";
CM_ SG_ 2416045727 M2P_DIAG_BYTE4_15 "MBMU给PC的诊断报文字节4";
CM_ SG_ 2416045727 M2P_DIAG_BYTE5_15 "MBMU给PC的诊断报文字节5";
CM_ SG_ 2416045727 M2P_DIAG_BYTE6_15 "MBMU给PC的诊断报文字节6";
CM_ SG_ 2416045727 M2P_DIAG_BYTE7_15 "MBMU给PC的诊断报文字节7";
CM_ SG_ 2416045727 M2P_DIAG_BYTE8_15 "MBMU给PC的诊断报文字节8";
CM_ SG_ 2416045728 M2P_DIAG_BYTE1_16 "MBMU给PC的诊断报文字节1";
CM_ SG_ 2416045728 M2P_DIAG_BYTE2_16 "MBMU给PC的诊断报文字节2";
CM_ SG_ 2416045728 M2P_DIAG_BYTE3_16 "MBMU给PC的诊断报文字节3";
CM_ SG_ 2416045728 M2P_DIAG_BYTE4_16 "MBMU给PC的诊断报文字节4";
CM_ SG_ 2416045728 M2P_DIAG_BYTE5_16 "MBMU给PC的诊断报文字节5";
CM_ SG_ 2416045728 M2P_DIAG_BYTE6_16 "MBMU给PC的诊断报文字节6";
CM_ SG_ 2416045728 M2P_DIAG_BYTE7_16 "MBMU给PC的诊断报文字节7";
CM_ SG_ 2416045728 M2P_DIAG_BYTE8_16 "MBMU给PC的诊断报文字节8";
CM_ SG_ 2416045729 M2P_DIAG_BYTE1_17 "MBMU给PC的诊断报文字节1";
CM_ SG_ 2416045729 M2P_DIAG_BYTE2_17 "MBMU给PC的诊断报文字节2";
CM_ SG_ 2416045729 M2P_DIAG_BYTE3_17 "MBMU给PC的诊断报文字节3";
CM_ SG_ 2416045729 M2P_DIAG_BYTE4_17 "MBMU给PC的诊断报文字节4";
CM_ SG_ 2416045729 M2P_DIAG_BYTE5_17 "MBMU给PC的诊断报文字节5";
CM_ SG_ 2416045729 M2P_DIAG_BYTE6_17 "MBMU给PC的诊断报文字节6";
CM_ SG_ 2416045729 M2P_DIAG_BYTE7_17 "MBMU给PC的诊断报文字节7";
CM_ SG_ 2416045729 M2P_DIAG_BYTE8_17 "MBMU给PC的诊断报文字节8";
CM_ SG_ 2416045730 M2P_DIAG_BYTE1_18 "MBMU给PC的诊断报文字节1";
CM_ SG_ 2416045730 M2P_DIAG_BYTE2_18 "MBMU给PC的诊断报文字节2";
CM_ SG_ 2416045730 M2P_DIAG_BYTE3_18 "MBMU给PC的诊断报文字节3";
CM_ SG_ 2416045730 M2P_DIAG_BYTE4_18 "MBMU给PC的诊断报文字节4";
CM_ SG_ 2416045730 M2P_DIAG_BYTE5_18 "MBMU给PC的诊断报文字节5";
CM_ SG_ 2416045730 M2P_DIAG_BYTE6_18 "MBMU给PC的诊断报文字节6";
CM_ SG_ 2416045730 M2P_DIAG_BYTE7_18 "MBMU给PC的诊断报文字节7";
CM_ SG_ 2416045730 M2P_DIAG_BYTE8_18 "MBMU给PC的诊断报文字节8";
CM_ SG_ 2416045731 M2P_DIAG_BYTE1_19 "MBMU给PC的诊断报文字节1";
CM_ SG_ 2416045731 M2P_DIAG_BYTE2_19 "MBMU给PC的诊断报文字节2";
CM_ SG_ 2416045731 M2P_DIAG_BYTE3_19 "MBMU给PC的诊断报文字节3";
CM_ SG_ 2416045731 M2P_DIAG_BYTE4_19 "MBMU给PC的诊断报文字节4";
CM_ SG_ 2416045731 M2P_DIAG_BYTE5_19 "MBMU给PC的诊断报文字节5";
CM_ SG_ 2416045731 M2P_DIAG_BYTE6_19 "MBMU给PC的诊断报文字节6";
CM_ SG_ 2416045731 M2P_DIAG_BYTE7_19 "MBMU给PC的诊断报文字节7";
CM_ SG_ 2416045731 M2P_DIAG_BYTE8_19 "MBMU给PC的诊断报文字节8";
CM_ SG_ 2416045732 M2P_DIAG_BYTE1_20 "MBMU给PC的诊断报文字节1";
CM_ SG_ 2416045732 M2P_DIAG_BYTE2_20 "MBMU给PC的诊断报文字节2";
CM_ SG_ 2416045732 M2P_DIAG_BYTE3_20 "MBMU给PC的诊断报文字节3";
CM_ SG_ 2416045732 M2P_DIAG_BYTE4_20 "MBMU给PC的诊断报文字节4";
CM_ SG_ 2416045732 M2P_DIAG_BYTE5_20 "MBMU给PC的诊断报文字节5";
CM_ SG_ 2416045732 M2P_DIAG_BYTE6_20 "MBMU给PC的诊断报文字节6";
CM_ SG_ 2416045732 M2P_DIAG_BYTE7_20 "MBMU给PC的诊断报文字节7";
CM_ SG_ 2416045732 M2P_DIAG_BYTE8_20 "MBMU给PC的诊断报文字节8";
CM_ SG_ 2416045733 M2P_DIAG_BYTE1_21 "MBMU给PC的诊断报文字节1";
CM_ SG_ 2416045733 M2P_DIAG_BYTE2_21 "MBMU给PC的诊断报文字节2";
CM_ SG_ 2416045733 M2P_DIAG_BYTE3_21 "MBMU给PC的诊断报文字节3";
CM_ SG_ 2416045733 M2P_DIAG_BYTE4_21 "MBMU给PC的诊断报文字节4";
CM_ SG_ 2416045733 M2P_DIAG_BYTE5_21 "MBMU给PC的诊断报文字节5";
CM_ SG_ 2416045733 M2P_DIAG_BYTE6_21 "MBMU给PC的诊断报文字节6";
CM_ SG_ 2416045733 M2P_DIAG_BYTE7_21 "MBMU给PC的诊断报文字节7";
CM_ SG_ 2416045733 M2P_DIAG_BYTE8_21 "MBMU给PC的诊断报文字节8";
CM_ SG_ 2416045734 M2P_DIAG_BYTE1_22 "MBMU给PC的诊断报文字节1";
CM_ SG_ 2416045734 M2P_DIAG_BYTE2_22 "MBMU给PC的诊断报文字节2";
CM_ SG_ 2416045734 M2P_DIAG_BYTE3_22 "MBMU给PC的诊断报文字节3";
CM_ SG_ 2416045734 M2P_DIAG_BYTE4_22 "MBMU给PC的诊断报文字节4";
CM_ SG_ 2416045734 M2P_DIAG_BYTE5_22 "MBMU给PC的诊断报文字节5";
CM_ SG_ 2416045734 M2P_DIAG_BYTE6_22 "MBMU给PC的诊断报文字节6";
CM_ SG_ 2416045734 M2P_DIAG_BYTE7_22 "MBMU给PC的诊断报文字节7";
CM_ SG_ 2416045734 M2P_DIAG_BYTE8_22 "MBMU给PC的诊断报文字节8";
CM_ SG_ 2416045735 M2P_DIAG_BYTE1_23 "MBMU给PC的诊断报文字节1";
CM_ SG_ 2416045735 M2P_DIAG_BYTE2_23 "MBMU给PC的诊断报文字节2";
CM_ SG_ 2416045735 M2P_DIAG_BYTE3_23 "MBMU给PC的诊断报文字节3";
CM_ SG_ 2416045735 M2P_DIAG_BYTE4_23 "MBMU给PC的诊断报文字节4";
CM_ SG_ 2416045735 M2P_DIAG_BYTE5_23 "MBMU给PC的诊断报文字节5";
CM_ SG_ 2416045735 M2P_DIAG_BYTE6_23 "MBMU给PC的诊断报文字节6";
CM_ SG_ 2416045735 M2P_DIAG_BYTE7_23 "MBMU给PC的诊断报文字节7";
CM_ SG_ 2416045735 M2P_DIAG_BYTE8_23 "MBMU给PC的诊断报文字节8";
CM_ SG_ 2416045736 M2P_DIAG_BYTE1_24 "MBMU给PC的诊断报文字节1";
CM_ SG_ 2416045736 M2P_DIAG_BYTE2_24 "MBMU给PC的诊断报文字节2";
CM_ SG_ 2416045736 M2P_DIAG_BYTE3_24 "MBMU给PC的诊断报文字节3";
CM_ SG_ 2416045736 M2P_DIAG_BYTE4_24 "MBMU给PC的诊断报文字节4";
CM_ SG_ 2416045736 M2P_DIAG_BYTE5_24 "MBMU给PC的诊断报文字节5";
CM_ SG_ 2416045736 M2P_DIAG_BYTE6_24 "MBMU给PC的诊断报文字节6";
CM_ SG_ 2416045736 M2P_DIAG_BYTE7_24 "MBMU给PC的诊断报文字节7";
CM_ SG_ 2416045736 M2P_DIAG_BYTE8_24 "MBMU给PC的诊断报文字节8";
CM_ SG_ 2416045737 M2P_DIAG_BYTE1_25 "MBMU给PC的诊断报文字节1";
CM_ SG_ 2416045737 M2P_DIAG_BYTE2_25 "MBMU给PC的诊断报文字节2";
CM_ SG_ 2416045737 M2P_DIAG_BYTE3_25 "MBMU给PC的诊断报文字节3";
CM_ SG_ 2416045737 M2P_DIAG_BYTE4_25 "MBMU给PC的诊断报文字节4";
CM_ SG_ 2416045737 M2P_DIAG_BYTE5_25 "MBMU给PC的诊断报文字节5";
CM_ SG_ 2416045737 M2P_DIAG_BYTE6_25 "MBMU给PC的诊断报文字节6";
CM_ SG_ 2416045737 M2P_DIAG_BYTE7_25 "MBMU给PC的诊断报文字节7";
CM_ SG_ 2416045737 M2P_DIAG_BYTE8_25 "MBMU给PC的诊断报文字节8";
CM_ SG_ 2416045738 M2P_DIAG_BYTE1_26 "MBMU给PC的诊断报文字节1";
CM_ SG_ 2416045738 M2P_DIAG_BYTE2_26 "MBMU给PC的诊断报文字节2";
CM_ SG_ 2416045738 M2P_DIAG_BYTE3_26 "MBMU给PC的诊断报文字节3";
CM_ SG_ 2416045738 M2P_DIAG_BYTE4_26 "MBMU给PC的诊断报文字节4";
CM_ SG_ 2416045738 M2P_DIAG_BYTE5_26 "MBMU给PC的诊断报文字节5";
CM_ SG_ 2416045738 M2P_DIAG_BYTE6_26 "MBMU给PC的诊断报文字节6";
CM_ SG_ 2416045738 M2P_DIAG_BYTE7_26 "MBMU给PC的诊断报文字节7";
CM_ SG_ 2416045738 M2P_DIAG_BYTE8_26 "MBMU给PC的诊断报文字节8";
CM_ SG_ 2416045739 M2P_DIAG_BYTE1_27 "MBMU给PC的诊断报文字节1";
CM_ SG_ 2416045739 M2P_DIAG_BYTE2_27 "MBMU给PC的诊断报文字节2";
CM_ SG_ 2416045739 M2P_DIAG_BYTE3_27 "MBMU给PC的诊断报文字节3";
CM_ SG_ 2416045739 M2P_DIAG_BYTE4_27 "MBMU给PC的诊断报文字节4";
CM_ SG_ 2416045739 M2P_DIAG_BYTE5_27 "MBMU给PC的诊断报文字节5";
CM_ SG_ 2416045739 M2P_DIAG_BYTE6_27 "MBMU给PC的诊断报文字节6";
CM_ SG_ 2416045739 M2P_DIAG_BYTE7_27 "MBMU给PC的诊断报文字节7";
CM_ SG_ 2416045739 M2P_DIAG_BYTE8_27 "MBMU给PC的诊断报文字节8";
CM_ SG_ 2416045740 M2P_DIAG_BYTE1_28 "MBMU给PC的诊断报文字节1";
CM_ SG_ 2416045740 M2P_DIAG_BYTE2_28 "MBMU给PC的诊断报文字节2";
CM_ SG_ 2416045740 M2P_DIAG_BYTE3_28 "MBMU给PC的诊断报文字节3";
CM_ SG_ 2416045740 M2P_DIAG_BYTE4_28 "MBMU给PC的诊断报文字节4";
CM_ SG_ 2416045740 M2P_DIAG_BYTE5_28 "MBMU给PC的诊断报文字节5";
CM_ SG_ 2416045740 M2P_DIAG_BYTE6_28 "MBMU给PC的诊断报文字节6";
CM_ SG_ 2416045740 M2P_DIAG_BYTE7_28 "MBMU给PC的诊断报文字节7";
CM_ SG_ 2416045740 M2P_DIAG_BYTE8_28 "MBMU给PC的诊断报文字节8";
CM_ SG_ 2416045741 M2P_DIAG_BYTE1_29 "MBMU给PC的诊断报文字节1";
CM_ SG_ 2416045741 M2P_DIAG_BYTE2_29 "MBMU给PC的诊断报文字节2";
CM_ SG_ 2416045741 M2P_DIAG_BYTE3_29 "MBMU给PC的诊断报文字节3";
CM_ SG_ 2416045741 M2P_DIAG_BYTE4_29 "MBMU给PC的诊断报文字节4";
CM_ SG_ 2416045741 M2P_DIAG_BYTE5_29 "MBMU给PC的诊断报文字节5";
CM_ SG_ 2416045741 M2P_DIAG_BYTE6_29 "MBMU给PC的诊断报文字节6";
CM_ SG_ 2416045741 M2P_DIAG_BYTE7_29 "MBMU给PC的诊断报文字节7";
CM_ SG_ 2416045741 M2P_DIAG_BYTE8_29 "MBMU给PC的诊断报文字节8";
CM_ SG_ 2416045742 M2P_DIAG_BYTE1_30 "MBMU给PC的诊断报文字节1";
CM_ SG_ 2416045742 M2P_DIAG_BYTE2_30 "MBMU给PC的诊断报文字节2";
CM_ SG_ 2416045742 M2P_DIAG_BYTE3_30 "MBMU给PC的诊断报文字节3";
CM_ SG_ 2416045742 M2P_DIAG_BYTE4_30 "MBMU给PC的诊断报文字节4";
CM_ SG_ 2416045742 M2P_DIAG_BYTE5_30 "MBMU给PC的诊断报文字节5";
CM_ SG_ 2416045742 M2P_DIAG_BYTE6_30 "MBMU给PC的诊断报文字节6";
CM_ SG_ 2416045742 M2P_DIAG_BYTE7_30 "MBMU给PC的诊断报文字节7";
CM_ SG_ 2416045742 M2P_DIAG_BYTE8_30 "MBMU给PC的诊断报文字节8";
CM_ SG_ 2416045743 M2P_DIAG_BYTE1_31 "MBMU给PC的诊断报文字节1";
CM_ SG_ 2416045743 M2P_DIAG_BYTE2_31 "MBMU给PC的诊断报文字节2";
CM_ SG_ 2416045743 M2P_DIAG_BYTE3_31 "MBMU给PC的诊断报文字节3";
CM_ SG_ 2416045743 M2P_DIAG_BYTE4_31 "MBMU给PC的诊断报文字节4";
CM_ SG_ 2416045743 M2P_DIAG_BYTE5_31 "MBMU给PC的诊断报文字节5";
CM_ SG_ 2416045743 M2P_DIAG_BYTE6_31 "MBMU给PC的诊断报文字节6";
CM_ SG_ 2416045743 M2P_DIAG_BYTE7_31 "MBMU给PC的诊断报文字节7";
CM_ SG_ 2416045743 M2P_DIAG_BYTE8_31 "MBMU给PC的诊断报文字节8";
CM_ SG_ 2416111249 M2P_Cfg1_SW_Ver_Byte1_01 "MBMU软件版本号最低字节Byte1对应ASCII码";
CM_ SG_ 2416111249 M2P_Cfg1_SW_Ver_Byte2_01 "MBMU软件版本号Byte2对应ASCII码";
CM_ SG_ 2416111249 M2P_Cfg1_SW_Ver_Byte3_01 "MBMU软件版本号Byte3对应ASCII码";
CM_ SG_ 2416111249 M2P_Cfg1_SW_Ver_Byte4_01 "MBMU软件版本号Byte4对应ASCII码";
CM_ SG_ 2416111249 M2P_Cfg1_SW_Ver_Byte5_01 "MBMU软件版本号Byte5对应ASCII码";
CM_ SG_ 2416111249 M2P_Cfg1_SW_Ver_Byte6_01 "MBMU软件版本号Byte6对应ASCII码";
CM_ SG_ 2416111249 M2P_Cfg1_SW_Ver_Byte7_01 "MBMU软件版本号Byte7对应ASCII码";
CM_ SG_ 2416111249 M2P_Cfg1_SW_Ver_Byte8_01 "MBMU软件版本号Byte8对应ASCII码";
CM_ SG_ 2416111250 M2P_Cfg1_SW_Ver_Byte1_02 "MBMU软件版本号最低字节Byte1对应ASCII码";
CM_ SG_ 2416111250 M2P_Cfg1_SW_Ver_Byte2_02 "MBMU软件版本号Byte2对应ASCII码";
CM_ SG_ 2416111250 M2P_Cfg1_SW_Ver_Byte3_02 "MBMU软件版本号Byte3对应ASCII码";
CM_ SG_ 2416111250 M2P_Cfg1_SW_Ver_Byte4_02 "MBMU软件版本号Byte4对应ASCII码";
CM_ SG_ 2416111250 M2P_Cfg1_SW_Ver_Byte5_02 "MBMU软件版本号Byte5对应ASCII码";
CM_ SG_ 2416111250 M2P_Cfg1_SW_Ver_Byte6_02 "MBMU软件版本号Byte6对应ASCII码";
CM_ SG_ 2416111250 M2P_Cfg1_SW_Ver_Byte7_02 "MBMU软件版本号Byte7对应ASCII码";
CM_ SG_ 2416111250 M2P_Cfg1_SW_Ver_Byte8_02 "MBMU软件版本号Byte8对应ASCII码";
CM_ SG_ 2416111251 M2P_Cfg1_SW_Ver_Byte1_03 "MBMU软件版本号最低字节Byte1对应ASCII码";
CM_ SG_ 2416111251 M2P_Cfg1_SW_Ver_Byte2_03 "MBMU软件版本号Byte2对应ASCII码";
CM_ SG_ 2416111251 M2P_Cfg1_SW_Ver_Byte3_03 "MBMU软件版本号Byte3对应ASCII码";
CM_ SG_ 2416111251 M2P_Cfg1_SW_Ver_Byte4_03 "MBMU软件版本号Byte4对应ASCII码";
CM_ SG_ 2416111251 M2P_Cfg1_SW_Ver_Byte5_03 "MBMU软件版本号Byte5对应ASCII码";
CM_ SG_ 2416111251 M2P_Cfg1_SW_Ver_Byte6_03 "MBMU软件版本号Byte6对应ASCII码";
CM_ SG_ 2416111251 M2P_Cfg1_SW_Ver_Byte7_03 "MBMU软件版本号Byte7对应ASCII码";
CM_ SG_ 2416111251 M2P_Cfg1_SW_Ver_Byte8_03 "MBMU软件版本号Byte8对应ASCII码";
CM_ SG_ 2416111252 M2P_Cfg1_SW_Ver_Byte1_04 "MBMU软件版本号最低字节Byte1对应ASCII码";
CM_ SG_ 2416111252 M2P_Cfg1_SW_Ver_Byte2_04 "MBMU软件版本号Byte2对应ASCII码";
CM_ SG_ 2416111252 M2P_Cfg1_SW_Ver_Byte3_04 "MBMU软件版本号Byte3对应ASCII码";
CM_ SG_ 2416111252 M2P_Cfg1_SW_Ver_Byte4_04 "MBMU软件版本号Byte4对应ASCII码";
CM_ SG_ 2416111252 M2P_Cfg1_SW_Ver_Byte5_04 "MBMU软件版本号Byte5对应ASCII码";
CM_ SG_ 2416111252 M2P_Cfg1_SW_Ver_Byte6_04 "MBMU软件版本号Byte6对应ASCII码";
CM_ SG_ 2416111252 M2P_Cfg1_SW_Ver_Byte7_04 "MBMU软件版本号Byte7对应ASCII码";
CM_ SG_ 2416111252 M2P_Cfg1_SW_Ver_Byte8_04 "MBMU软件版本号Byte8对应ASCII码";
CM_ SG_ 2416111253 M2P_Cfg1_SW_Ver_Byte1_05 "MBMU软件版本号最低字节Byte1对应ASCII码";
CM_ SG_ 2416111253 M2P_Cfg1_SW_Ver_Byte2_05 "MBMU软件版本号Byte2对应ASCII码";
CM_ SG_ 2416111253 M2P_Cfg1_SW_Ver_Byte3_05 "MBMU软件版本号Byte3对应ASCII码";
CM_ SG_ 2416111253 M2P_Cfg1_SW_Ver_Byte4_05 "MBMU软件版本号Byte4对应ASCII码";
CM_ SG_ 2416111253 M2P_Cfg1_SW_Ver_Byte5_05 "MBMU软件版本号Byte5对应ASCII码";
CM_ SG_ 2416111253 M2P_Cfg1_SW_Ver_Byte6_05 "MBMU软件版本号Byte6对应ASCII码";
CM_ SG_ 2416111253 M2P_Cfg1_SW_Ver_Byte7_05 "MBMU软件版本号Byte7对应ASCII码";
CM_ SG_ 2416111253 M2P_Cfg1_SW_Ver_Byte8_05 "MBMU软件版本号Byte8对应ASCII码";
CM_ SG_ 2416111254 M2P_Cfg1_SW_Ver_Byte1_06 "MBMU软件版本号最低字节Byte1对应ASCII码";
CM_ SG_ 2416111254 M2P_Cfg1_SW_Ver_Byte2_06 "MBMU软件版本号Byte2对应ASCII码";
CM_ SG_ 2416111254 M2P_Cfg1_SW_Ver_Byte3_06 "MBMU软件版本号Byte3对应ASCII码";
CM_ SG_ 2416111254 M2P_Cfg1_SW_Ver_Byte4_06 "MBMU软件版本号Byte4对应ASCII码";
CM_ SG_ 2416111254 M2P_Cfg1_SW_Ver_Byte5_06 "MBMU软件版本号Byte5对应ASCII码";
CM_ SG_ 2416111254 M2P_Cfg1_SW_Ver_Byte6_06 "MBMU软件版本号Byte6对应ASCII码";
CM_ SG_ 2416111254 M2P_Cfg1_SW_Ver_Byte7_06 "MBMU软件版本号Byte7对应ASCII码";
CM_ SG_ 2416111254 M2P_Cfg1_SW_Ver_Byte8_06 "MBMU软件版本号Byte8对应ASCII码";
CM_ SG_ 2416111255 M2P_Cfg1_SW_Ver_Byte1_07 "MBMU软件版本号最低字节Byte1对应ASCII码";
CM_ SG_ 2416111255 M2P_Cfg1_SW_Ver_Byte2_07 "MBMU软件版本号Byte2对应ASCII码";
CM_ SG_ 2416111255 M2P_Cfg1_SW_Ver_Byte3_07 "MBMU软件版本号Byte3对应ASCII码";
CM_ SG_ 2416111255 M2P_Cfg1_SW_Ver_Byte4_07 "MBMU软件版本号Byte4对应ASCII码";
CM_ SG_ 2416111255 M2P_Cfg1_SW_Ver_Byte5_07 "MBMU软件版本号Byte5对应ASCII码";
CM_ SG_ 2416111255 M2P_Cfg1_SW_Ver_Byte6_07 "MBMU软件版本号Byte6对应ASCII码";
CM_ SG_ 2416111255 M2P_Cfg1_SW_Ver_Byte7_07 "MBMU软件版本号Byte7对应ASCII码";
CM_ SG_ 2416111255 M2P_Cfg1_SW_Ver_Byte8_07 "MBMU软件版本号Byte8对应ASCII码";
CM_ SG_ 2416111256 M2P_Cfg1_SW_Ver_Byte1_08 "MBMU软件版本号最低字节Byte1对应ASCII码";
CM_ SG_ 2416111256 M2P_Cfg1_SW_Ver_Byte2_08 "MBMU软件版本号Byte2对应ASCII码";
CM_ SG_ 2416111256 M2P_Cfg1_SW_Ver_Byte3_08 "MBMU软件版本号Byte3对应ASCII码";
CM_ SG_ 2416111256 M2P_Cfg1_SW_Ver_Byte4_08 "MBMU软件版本号Byte4对应ASCII码";
CM_ SG_ 2416111256 M2P_Cfg1_SW_Ver_Byte5_08 "MBMU软件版本号Byte5对应ASCII码";
CM_ SG_ 2416111256 M2P_Cfg1_SW_Ver_Byte6_08 "MBMU软件版本号Byte6对应ASCII码";
CM_ SG_ 2416111256 M2P_Cfg1_SW_Ver_Byte7_08 "MBMU软件版本号Byte7对应ASCII码";
CM_ SG_ 2416111256 M2P_Cfg1_SW_Ver_Byte8_08 "MBMU软件版本号Byte8对应ASCII码";
CM_ SG_ 2416111257 M2P_Cfg1_SW_Ver_Byte1_09 "MBMU软件版本号最低字节Byte1对应ASCII码";
CM_ SG_ 2416111257 M2P_Cfg1_SW_Ver_Byte2_09 "MBMU软件版本号Byte2对应ASCII码";
CM_ SG_ 2416111257 M2P_Cfg1_SW_Ver_Byte3_09 "MBMU软件版本号Byte3对应ASCII码";
CM_ SG_ 2416111257 M2P_Cfg1_SW_Ver_Byte4_09 "MBMU软件版本号Byte4对应ASCII码";
CM_ SG_ 2416111257 M2P_Cfg1_SW_Ver_Byte5_09 "MBMU软件版本号Byte5对应ASCII码";
CM_ SG_ 2416111257 M2P_Cfg1_SW_Ver_Byte6_09 "MBMU软件版本号Byte6对应ASCII码";
CM_ SG_ 2416111257 M2P_Cfg1_SW_Ver_Byte7_09 "MBMU软件版本号Byte7对应ASCII码";
CM_ SG_ 2416111257 M2P_Cfg1_SW_Ver_Byte8_09 "MBMU软件版本号Byte8对应ASCII码";
CM_ SG_ 2416111258 M2P_Cfg1_SW_Ver_Byte1_10 "MBMU软件版本号最低字节Byte1对应ASCII码";
CM_ SG_ 2416111258 M2P_Cfg1_SW_Ver_Byte2_10 "MBMU软件版本号Byte2对应ASCII码";
CM_ SG_ 2416111258 M2P_Cfg1_SW_Ver_Byte3_10 "MBMU软件版本号Byte3对应ASCII码";
CM_ SG_ 2416111258 M2P_Cfg1_SW_Ver_Byte4_10 "MBMU软件版本号Byte4对应ASCII码";
CM_ SG_ 2416111258 M2P_Cfg1_SW_Ver_Byte5_10 "MBMU软件版本号Byte5对应ASCII码";
CM_ SG_ 2416111258 M2P_Cfg1_SW_Ver_Byte6_10 "MBMU软件版本号Byte6对应ASCII码";
CM_ SG_ 2416111258 M2P_Cfg1_SW_Ver_Byte7_10 "MBMU软件版本号Byte7对应ASCII码";
CM_ SG_ 2416111258 M2P_Cfg1_SW_Ver_Byte8_10 "MBMU软件版本号Byte8对应ASCII码";
CM_ SG_ 2416111259 M2P_Cfg1_SW_Ver_Byte1_11 "MBMU软件版本号最低字节Byte1对应ASCII码";
CM_ SG_ 2416111259 M2P_Cfg1_SW_Ver_Byte2_11 "MBMU软件版本号Byte2对应ASCII码";
CM_ SG_ 2416111259 M2P_Cfg1_SW_Ver_Byte3_11 "MBMU软件版本号Byte3对应ASCII码";
CM_ SG_ 2416111259 M2P_Cfg1_SW_Ver_Byte4_11 "MBMU软件版本号Byte4对应ASCII码";
CM_ SG_ 2416111259 M2P_Cfg1_SW_Ver_Byte5_11 "MBMU软件版本号Byte5对应ASCII码";
CM_ SG_ 2416111259 M2P_Cfg1_SW_Ver_Byte6_11 "MBMU软件版本号Byte6对应ASCII码";
CM_ SG_ 2416111259 M2P_Cfg1_SW_Ver_Byte7_11 "MBMU软件版本号Byte7对应ASCII码";
CM_ SG_ 2416111259 M2P_Cfg1_SW_Ver_Byte8_11 "MBMU软件版本号Byte8对应ASCII码";
CM_ SG_ 2416111260 M2P_Cfg1_SW_Ver_Byte1_12 "MBMU软件版本号最低字节Byte1对应ASCII码";
CM_ SG_ 2416111260 M2P_Cfg1_SW_Ver_Byte2_12 "MBMU软件版本号Byte2对应ASCII码";
CM_ SG_ 2416111260 M2P_Cfg1_SW_Ver_Byte3_12 "MBMU软件版本号Byte3对应ASCII码";
CM_ SG_ 2416111260 M2P_Cfg1_SW_Ver_Byte4_12 "MBMU软件版本号Byte4对应ASCII码";
CM_ SG_ 2416111260 M2P_Cfg1_SW_Ver_Byte5_12 "MBMU软件版本号Byte5对应ASCII码";
CM_ SG_ 2416111260 M2P_Cfg1_SW_Ver_Byte6_12 "MBMU软件版本号Byte6对应ASCII码";
CM_ SG_ 2416111260 M2P_Cfg1_SW_Ver_Byte7_12 "MBMU软件版本号Byte7对应ASCII码";
CM_ SG_ 2416111260 M2P_Cfg1_SW_Ver_Byte8_12 "MBMU软件版本号Byte8对应ASCII码";
CM_ SG_ 2416111261 M2P_Cfg1_SW_Ver_Byte1_13 "MBMU软件版本号最低字节Byte1对应ASCII码";
CM_ SG_ 2416111261 M2P_Cfg1_SW_Ver_Byte2_13 "MBMU软件版本号Byte2对应ASCII码";
CM_ SG_ 2416111261 M2P_Cfg1_SW_Ver_Byte3_13 "MBMU软件版本号Byte3对应ASCII码";
CM_ SG_ 2416111261 M2P_Cfg1_SW_Ver_Byte4_13 "MBMU软件版本号Byte4对应ASCII码";
CM_ SG_ 2416111261 M2P_Cfg1_SW_Ver_Byte5_13 "MBMU软件版本号Byte5对应ASCII码";
CM_ SG_ 2416111261 M2P_Cfg1_SW_Ver_Byte6_13 "MBMU软件版本号Byte6对应ASCII码";
CM_ SG_ 2416111261 M2P_Cfg1_SW_Ver_Byte7_13 "MBMU软件版本号Byte7对应ASCII码";
CM_ SG_ 2416111261 M2P_Cfg1_SW_Ver_Byte8_13 "MBMU软件版本号Byte8对应ASCII码";
CM_ SG_ 2416111262 M2P_Cfg1_SW_Ver_Byte1_14 "MBMU软件版本号最低字节Byte1对应ASCII码";
CM_ SG_ 2416111262 M2P_Cfg1_SW_Ver_Byte2_14 "MBMU软件版本号Byte2对应ASCII码";
CM_ SG_ 2416111262 M2P_Cfg1_SW_Ver_Byte3_14 "MBMU软件版本号Byte3对应ASCII码";
CM_ SG_ 2416111262 M2P_Cfg1_SW_Ver_Byte4_14 "MBMU软件版本号Byte4对应ASCII码";
CM_ SG_ 2416111262 M2P_Cfg1_SW_Ver_Byte5_14 "MBMU软件版本号Byte5对应ASCII码";
CM_ SG_ 2416111262 M2P_Cfg1_SW_Ver_Byte6_14 "MBMU软件版本号Byte6对应ASCII码";
CM_ SG_ 2416111262 M2P_Cfg1_SW_Ver_Byte7_14 "MBMU软件版本号Byte7对应ASCII码";
CM_ SG_ 2416111262 M2P_Cfg1_SW_Ver_Byte8_14 "MBMU软件版本号Byte8对应ASCII码";
CM_ SG_ 2416111263 M2P_Cfg1_SW_Ver_Byte1_15 "MBMU软件版本号最低字节Byte1对应ASCII码";
CM_ SG_ 2416111263 M2P_Cfg1_SW_Ver_Byte2_15 "MBMU软件版本号Byte2对应ASCII码";
CM_ SG_ 2416111263 M2P_Cfg1_SW_Ver_Byte3_15 "MBMU软件版本号Byte3对应ASCII码";
CM_ SG_ 2416111263 M2P_Cfg1_SW_Ver_Byte4_15 "MBMU软件版本号Byte4对应ASCII码";
CM_ SG_ 2416111263 M2P_Cfg1_SW_Ver_Byte5_15 "MBMU软件版本号Byte5对应ASCII码";
CM_ SG_ 2416111263 M2P_Cfg1_SW_Ver_Byte6_15 "MBMU软件版本号Byte6对应ASCII码";
CM_ SG_ 2416111263 M2P_Cfg1_SW_Ver_Byte7_15 "MBMU软件版本号Byte7对应ASCII码";
CM_ SG_ 2416111263 M2P_Cfg1_SW_Ver_Byte8_15 "MBMU软件版本号Byte8对应ASCII码";
CM_ SG_ 2416111264 M2P_Cfg1_SW_Ver_Byte1_16 "MBMU软件版本号最低字节Byte1对应ASCII码";
CM_ SG_ 2416111264 M2P_Cfg1_SW_Ver_Byte2_16 "MBMU软件版本号Byte2对应ASCII码";
CM_ SG_ 2416111264 M2P_Cfg1_SW_Ver_Byte3_16 "MBMU软件版本号Byte3对应ASCII码";
CM_ SG_ 2416111264 M2P_Cfg1_SW_Ver_Byte4_16 "MBMU软件版本号Byte4对应ASCII码";
CM_ SG_ 2416111264 M2P_Cfg1_SW_Ver_Byte5_16 "MBMU软件版本号Byte5对应ASCII码";
CM_ SG_ 2416111264 M2P_Cfg1_SW_Ver_Byte6_16 "MBMU软件版本号Byte6对应ASCII码";
CM_ SG_ 2416111264 M2P_Cfg1_SW_Ver_Byte7_16 "MBMU软件版本号Byte7对应ASCII码";
CM_ SG_ 2416111264 M2P_Cfg1_SW_Ver_Byte8_16 "MBMU软件版本号Byte8对应ASCII码";
CM_ SG_ 2416111265 M2P_Cfg1_SW_Ver_Byte1_17 "MBMU软件版本号最低字节Byte1对应ASCII码";
CM_ SG_ 2416111265 M2P_Cfg1_SW_Ver_Byte2_17 "MBMU软件版本号Byte2对应ASCII码";
CM_ SG_ 2416111265 M2P_Cfg1_SW_Ver_Byte3_17 "MBMU软件版本号Byte3对应ASCII码";
CM_ SG_ 2416111265 M2P_Cfg1_SW_Ver_Byte4_17 "MBMU软件版本号Byte4对应ASCII码";
CM_ SG_ 2416111265 M2P_Cfg1_SW_Ver_Byte5_17 "MBMU软件版本号Byte5对应ASCII码";
CM_ SG_ 2416111265 M2P_Cfg1_SW_Ver_Byte6_17 "MBMU软件版本号Byte6对应ASCII码";
CM_ SG_ 2416111265 M2P_Cfg1_SW_Ver_Byte7_17 "MBMU软件版本号Byte7对应ASCII码";
CM_ SG_ 2416111265 M2P_Cfg1_SW_Ver_Byte8_17 "MBMU软件版本号Byte8对应ASCII码";
CM_ SG_ 2416111266 M2P_Cfg1_SW_Ver_Byte1_18 "MBMU软件版本号最低字节Byte1对应ASCII码";
CM_ SG_ 2416111266 M2P_Cfg1_SW_Ver_Byte2_18 "MBMU软件版本号Byte2对应ASCII码";
CM_ SG_ 2416111266 M2P_Cfg1_SW_Ver_Byte3_18 "MBMU软件版本号Byte3对应ASCII码";
CM_ SG_ 2416111266 M2P_Cfg1_SW_Ver_Byte4_18 "MBMU软件版本号Byte4对应ASCII码";
CM_ SG_ 2416111266 M2P_Cfg1_SW_Ver_Byte5_18 "MBMU软件版本号Byte5对应ASCII码";
CM_ SG_ 2416111266 M2P_Cfg1_SW_Ver_Byte6_18 "MBMU软件版本号Byte6对应ASCII码";
CM_ SG_ 2416111266 M2P_Cfg1_SW_Ver_Byte7_18 "MBMU软件版本号Byte7对应ASCII码";
CM_ SG_ 2416111266 M2P_Cfg1_SW_Ver_Byte8_18 "MBMU软件版本号Byte8对应ASCII码";
CM_ SG_ 2416111267 M2P_Cfg1_SW_Ver_Byte1_19 "MBMU软件版本号最低字节Byte1对应ASCII码";
CM_ SG_ 2416111267 M2P_Cfg1_SW_Ver_Byte2_19 "MBMU软件版本号Byte2对应ASCII码";
CM_ SG_ 2416111267 M2P_Cfg1_SW_Ver_Byte3_19 "MBMU软件版本号Byte3对应ASCII码";
CM_ SG_ 2416111267 M2P_Cfg1_SW_Ver_Byte4_19 "MBMU软件版本号Byte4对应ASCII码";
CM_ SG_ 2416111267 M2P_Cfg1_SW_Ver_Byte5_19 "MBMU软件版本号Byte5对应ASCII码";
CM_ SG_ 2416111267 M2P_Cfg1_SW_Ver_Byte6_19 "MBMU软件版本号Byte6对应ASCII码";
CM_ SG_ 2416111267 M2P_Cfg1_SW_Ver_Byte7_19 "MBMU软件版本号Byte7对应ASCII码";
CM_ SG_ 2416111267 M2P_Cfg1_SW_Ver_Byte8_19 "MBMU软件版本号Byte8对应ASCII码";
CM_ SG_ 2416111268 M2P_Cfg1_SW_Ver_Byte1_20 "MBMU软件版本号最低字节Byte1对应ASCII码";
CM_ SG_ 2416111268 M2P_Cfg1_SW_Ver_Byte2_20 "MBMU软件版本号Byte2对应ASCII码";
CM_ SG_ 2416111268 M2P_Cfg1_SW_Ver_Byte3_20 "MBMU软件版本号Byte3对应ASCII码";
CM_ SG_ 2416111268 M2P_Cfg1_SW_Ver_Byte4_20 "MBMU软件版本号Byte4对应ASCII码";
CM_ SG_ 2416111268 M2P_Cfg1_SW_Ver_Byte5_20 "MBMU软件版本号Byte5对应ASCII码";
CM_ SG_ 2416111268 M2P_Cfg1_SW_Ver_Byte6_20 "MBMU软件版本号Byte6对应ASCII码";
CM_ SG_ 2416111268 M2P_Cfg1_SW_Ver_Byte7_20 "MBMU软件版本号Byte7对应ASCII码";
CM_ SG_ 2416111268 M2P_Cfg1_SW_Ver_Byte8_20 "MBMU软件版本号Byte8对应ASCII码";
CM_ SG_ 2416111269 M2P_Cfg1_SW_Ver_Byte1_21 "MBMU软件版本号最低字节Byte1对应ASCII码";
CM_ SG_ 2416111269 M2P_Cfg1_SW_Ver_Byte2_21 "MBMU软件版本号Byte2对应ASCII码";
CM_ SG_ 2416111269 M2P_Cfg1_SW_Ver_Byte3_21 "MBMU软件版本号Byte3对应ASCII码";
CM_ SG_ 2416111269 M2P_Cfg1_SW_Ver_Byte4_21 "MBMU软件版本号Byte4对应ASCII码";
CM_ SG_ 2416111269 M2P_Cfg1_SW_Ver_Byte5_21 "MBMU软件版本号Byte5对应ASCII码";
CM_ SG_ 2416111269 M2P_Cfg1_SW_Ver_Byte6_21 "MBMU软件版本号Byte6对应ASCII码";
CM_ SG_ 2416111269 M2P_Cfg1_SW_Ver_Byte7_21 "MBMU软件版本号Byte7对应ASCII码";
CM_ SG_ 2416111269 M2P_Cfg1_SW_Ver_Byte8_21 "MBMU软件版本号Byte8对应ASCII码";
CM_ SG_ 2416111270 M2P_Cfg1_SW_Ver_Byte1_22 "MBMU软件版本号最低字节Byte1对应ASCII码";
CM_ SG_ 2416111270 M2P_Cfg1_SW_Ver_Byte2_22 "MBMU软件版本号Byte2对应ASCII码";
CM_ SG_ 2416111270 M2P_Cfg1_SW_Ver_Byte3_22 "MBMU软件版本号Byte3对应ASCII码";
CM_ SG_ 2416111270 M2P_Cfg1_SW_Ver_Byte4_22 "MBMU软件版本号Byte4对应ASCII码";
CM_ SG_ 2416111270 M2P_Cfg1_SW_Ver_Byte5_22 "MBMU软件版本号Byte5对应ASCII码";
CM_ SG_ 2416111270 M2P_Cfg1_SW_Ver_Byte6_22 "MBMU软件版本号Byte6对应ASCII码";
CM_ SG_ 2416111270 M2P_Cfg1_SW_Ver_Byte7_22 "MBMU软件版本号Byte7对应ASCII码";
CM_ SG_ 2416111270 M2P_Cfg1_SW_Ver_Byte8_22 "MBMU软件版本号Byte8对应ASCII码";
CM_ SG_ 2416111271 M2P_Cfg1_SW_Ver_Byte1_23 "MBMU软件版本号最低字节Byte1对应ASCII码";
CM_ SG_ 2416111271 M2P_Cfg1_SW_Ver_Byte2_23 "MBMU软件版本号Byte2对应ASCII码";
CM_ SG_ 2416111271 M2P_Cfg1_SW_Ver_Byte3_23 "MBMU软件版本号Byte3对应ASCII码";
CM_ SG_ 2416111271 M2P_Cfg1_SW_Ver_Byte4_23 "MBMU软件版本号Byte4对应ASCII码";
CM_ SG_ 2416111271 M2P_Cfg1_SW_Ver_Byte5_23 "MBMU软件版本号Byte5对应ASCII码";
CM_ SG_ 2416111271 M2P_Cfg1_SW_Ver_Byte6_23 "MBMU软件版本号Byte6对应ASCII码";
CM_ SG_ 2416111271 M2P_Cfg1_SW_Ver_Byte7_23 "MBMU软件版本号Byte7对应ASCII码";
CM_ SG_ 2416111271 M2P_Cfg1_SW_Ver_Byte8_23 "MBMU软件版本号Byte8对应ASCII码";
CM_ SG_ 2416111272 M2P_Cfg1_SW_Ver_Byte1_24 "MBMU软件版本号最低字节Byte1对应ASCII码";
CM_ SG_ 2416111272 M2P_Cfg1_SW_Ver_Byte2_24 "MBMU软件版本号Byte2对应ASCII码";
CM_ SG_ 2416111272 M2P_Cfg1_SW_Ver_Byte3_24 "MBMU软件版本号Byte3对应ASCII码";
CM_ SG_ 2416111272 M2P_Cfg1_SW_Ver_Byte4_24 "MBMU软件版本号Byte4对应ASCII码";
CM_ SG_ 2416111272 M2P_Cfg1_SW_Ver_Byte5_24 "MBMU软件版本号Byte5对应ASCII码";
CM_ SG_ 2416111272 M2P_Cfg1_SW_Ver_Byte6_24 "MBMU软件版本号Byte6对应ASCII码";
CM_ SG_ 2416111272 M2P_Cfg1_SW_Ver_Byte7_24 "MBMU软件版本号Byte7对应ASCII码";
CM_ SG_ 2416111272 M2P_Cfg1_SW_Ver_Byte8_24 "MBMU软件版本号Byte8对应ASCII码";
CM_ SG_ 2416111273 M2P_Cfg1_SW_Ver_Byte1_25 "MBMU软件版本号最低字节Byte1对应ASCII码";
CM_ SG_ 2416111273 M2P_Cfg1_SW_Ver_Byte2_25 "MBMU软件版本号Byte2对应ASCII码";
CM_ SG_ 2416111273 M2P_Cfg1_SW_Ver_Byte3_25 "MBMU软件版本号Byte3对应ASCII码";
CM_ SG_ 2416111273 M2P_Cfg1_SW_Ver_Byte4_25 "MBMU软件版本号Byte4对应ASCII码";
CM_ SG_ 2416111273 M2P_Cfg1_SW_Ver_Byte5_25 "MBMU软件版本号Byte5对应ASCII码";
CM_ SG_ 2416111273 M2P_Cfg1_SW_Ver_Byte6_25 "MBMU软件版本号Byte6对应ASCII码";
CM_ SG_ 2416111273 M2P_Cfg1_SW_Ver_Byte7_25 "MBMU软件版本号Byte7对应ASCII码";
CM_ SG_ 2416111273 M2P_Cfg1_SW_Ver_Byte8_25 "MBMU软件版本号Byte8对应ASCII码";
CM_ SG_ 2416111274 M2P_Cfg1_SW_Ver_Byte1_26 "MBMU软件版本号最低字节Byte1对应ASCII码";
CM_ SG_ 2416111274 M2P_Cfg1_SW_Ver_Byte2_26 "MBMU软件版本号Byte2对应ASCII码";
CM_ SG_ 2416111274 M2P_Cfg1_SW_Ver_Byte3_26 "MBMU软件版本号Byte3对应ASCII码";
CM_ SG_ 2416111274 M2P_Cfg1_SW_Ver_Byte4_26 "MBMU软件版本号Byte4对应ASCII码";
CM_ SG_ 2416111274 M2P_Cfg1_SW_Ver_Byte5_26 "MBMU软件版本号Byte5对应ASCII码";
CM_ SG_ 2416111274 M2P_Cfg1_SW_Ver_Byte6_26 "MBMU软件版本号Byte6对应ASCII码";
CM_ SG_ 2416111274 M2P_Cfg1_SW_Ver_Byte7_26 "MBMU软件版本号Byte7对应ASCII码";
CM_ SG_ 2416111274 M2P_Cfg1_SW_Ver_Byte8_26 "MBMU软件版本号Byte8对应ASCII码";
CM_ SG_ 2416111275 M2P_Cfg1_SW_Ver_Byte1_27 "MBMU软件版本号最低字节Byte1对应ASCII码";
CM_ SG_ 2416111275 M2P_Cfg1_SW_Ver_Byte2_27 "MBMU软件版本号Byte2对应ASCII码";
CM_ SG_ 2416111275 M2P_Cfg1_SW_Ver_Byte3_27 "MBMU软件版本号Byte3对应ASCII码";
CM_ SG_ 2416111275 M2P_Cfg1_SW_Ver_Byte4_27 "MBMU软件版本号Byte4对应ASCII码";
CM_ SG_ 2416111275 M2P_Cfg1_SW_Ver_Byte5_27 "MBMU软件版本号Byte5对应ASCII码";
CM_ SG_ 2416111275 M2P_Cfg1_SW_Ver_Byte6_27 "MBMU软件版本号Byte6对应ASCII码";
CM_ SG_ 2416111275 M2P_Cfg1_SW_Ver_Byte7_27 "MBMU软件版本号Byte7对应ASCII码";
CM_ SG_ 2416111275 M2P_Cfg1_SW_Ver_Byte8_27 "MBMU软件版本号Byte8对应ASCII码";
CM_ SG_ 2416111276 M2P_Cfg1_SW_Ver_Byte1_28 "MBMU软件版本号最低字节Byte1对应ASCII码";
CM_ SG_ 2416111276 M2P_Cfg1_SW_Ver_Byte2_28 "MBMU软件版本号Byte2对应ASCII码";
CM_ SG_ 2416111276 M2P_Cfg1_SW_Ver_Byte3_28 "MBMU软件版本号Byte3对应ASCII码";
CM_ SG_ 2416111276 M2P_Cfg1_SW_Ver_Byte4_28 "MBMU软件版本号Byte4对应ASCII码";
CM_ SG_ 2416111276 M2P_Cfg1_SW_Ver_Byte5_28 "MBMU软件版本号Byte5对应ASCII码";
CM_ SG_ 2416111276 M2P_Cfg1_SW_Ver_Byte6_28 "MBMU软件版本号Byte6对应ASCII码";
CM_ SG_ 2416111276 M2P_Cfg1_SW_Ver_Byte7_28 "MBMU软件版本号Byte7对应ASCII码";
CM_ SG_ 2416111276 M2P_Cfg1_SW_Ver_Byte8_28 "MBMU软件版本号Byte8对应ASCII码";
CM_ SG_ 2416111277 M2P_Cfg1_SW_Ver_Byte1_29 "MBMU软件版本号最低字节Byte1对应ASCII码";
CM_ SG_ 2416111277 M2P_Cfg1_SW_Ver_Byte2_29 "MBMU软件版本号Byte2对应ASCII码";
CM_ SG_ 2416111277 M2P_Cfg1_SW_Ver_Byte3_29 "MBMU软件版本号Byte3对应ASCII码";
CM_ SG_ 2416111277 M2P_Cfg1_SW_Ver_Byte4_29 "MBMU软件版本号Byte4对应ASCII码";
CM_ SG_ 2416111277 M2P_Cfg1_SW_Ver_Byte5_29 "MBMU软件版本号Byte5对应ASCII码";
CM_ SG_ 2416111277 M2P_Cfg1_SW_Ver_Byte6_29 "MBMU软件版本号Byte6对应ASCII码";
CM_ SG_ 2416111277 M2P_Cfg1_SW_Ver_Byte7_29 "MBMU软件版本号Byte7对应ASCII码";
CM_ SG_ 2416111277 M2P_Cfg1_SW_Ver_Byte8_29 "MBMU软件版本号Byte8对应ASCII码";
CM_ SG_ 2416111278 M2P_Cfg1_SW_Ver_Byte1_30 "MBMU软件版本号最低字节Byte1对应ASCII码";
CM_ SG_ 2416111278 M2P_Cfg1_SW_Ver_Byte2_30 "MBMU软件版本号Byte2对应ASCII码";
CM_ SG_ 2416111278 M2P_Cfg1_SW_Ver_Byte3_30 "MBMU软件版本号Byte3对应ASCII码";
CM_ SG_ 2416111278 M2P_Cfg1_SW_Ver_Byte4_30 "MBMU软件版本号Byte4对应ASCII码";
CM_ SG_ 2416111278 M2P_Cfg1_SW_Ver_Byte5_30 "MBMU软件版本号Byte5对应ASCII码";
CM_ SG_ 2416111278 M2P_Cfg1_SW_Ver_Byte6_30 "MBMU软件版本号Byte6对应ASCII码";
CM_ SG_ 2416111278 M2P_Cfg1_SW_Ver_Byte7_30 "MBMU软件版本号Byte7对应ASCII码";
CM_ SG_ 2416111278 M2P_Cfg1_SW_Ver_Byte8_30 "MBMU软件版本号Byte8对应ASCII码";
CM_ SG_ 2416111279 M2P_Cfg1_SW_Ver_Byte1_31 "MBMU软件版本号最低字节Byte1对应ASCII码";
CM_ SG_ 2416111279 M2P_Cfg1_SW_Ver_Byte2_31 "MBMU软件版本号Byte2对应ASCII码";
CM_ SG_ 2416111279 M2P_Cfg1_SW_Ver_Byte3_31 "MBMU软件版本号Byte3对应ASCII码";
CM_ SG_ 2416111279 M2P_Cfg1_SW_Ver_Byte4_31 "MBMU软件版本号Byte4对应ASCII码";
CM_ SG_ 2416111279 M2P_Cfg1_SW_Ver_Byte5_31 "MBMU软件版本号Byte5对应ASCII码";
CM_ SG_ 2416111279 M2P_Cfg1_SW_Ver_Byte6_31 "MBMU软件版本号Byte6对应ASCII码";
CM_ SG_ 2416111279 M2P_Cfg1_SW_Ver_Byte7_31 "MBMU软件版本号Byte7对应ASCII码";
CM_ SG_ 2416111279 M2P_Cfg1_SW_Ver_Byte8_31 "MBMU软件版本号Byte8对应ASCII码";
CM_ SG_ 2416176785 M2P_Cfg2_SW_Ver_Byte9_01 "MBMU软件版本号Byte9对应ASCII码";
CM_ SG_ 2416176785 M2P_Cfg2_SW_Ver_Byte10_01 "MBMU软件版本号Byte10对应ASCII码";
CM_ SG_ 2416176785 M2P_Cfg2_SW_Ver_Byte11_01 "MBMU软件版本号Byte11对应ASCII码";
CM_ SG_ 2416176785 M2P_Cfg2_SW_Ver_Byte12_01 "MBMU软件版本号Byte12对应ASCII码";
CM_ SG_ 2416176785 M2P_Cfg2_SW_Ver_Byte13_01 "MBMU软件版本号Byte13对应ASCII码";
CM_ SG_ 2416176785 M2P_Cfg2_SW_Ver_Byte14_01 "MBMU软件版本号Byte14对应ASCII码";
CM_ SG_ 2416176785 M2P_Cfg2_SW_Ver_Byte15_01 "MBMU软件版本号Byte15对应ASCII码";
CM_ SG_ 2416176785 M2P_Cfg2_SW_Ver_Byte16_01 "MBMU软件版本号最高字节Byte16对应ASCII码";
CM_ SG_ 2416176786 M2P_Cfg2_SW_Ver_Byte9_02 "MBMU软件版本号Byte9对应ASCII码";
CM_ SG_ 2416176786 M2P_Cfg2_SW_Ver_Byte10_02 "MBMU软件版本号Byte10对应ASCII码";
CM_ SG_ 2416176786 M2P_Cfg2_SW_Ver_Byte11_02 "MBMU软件版本号Byte11对应ASCII码";
CM_ SG_ 2416176786 M2P_Cfg2_SW_Ver_Byte12_02 "MBMU软件版本号Byte12对应ASCII码";
CM_ SG_ 2416176786 M2P_Cfg2_SW_Ver_Byte13_02 "MBMU软件版本号Byte13对应ASCII码";
CM_ SG_ 2416176786 M2P_Cfg2_SW_Ver_Byte14_02 "MBMU软件版本号Byte14对应ASCII码";
CM_ SG_ 2416176786 M2P_Cfg2_SW_Ver_Byte15_02 "MBMU软件版本号Byte15对应ASCII码";
CM_ SG_ 2416176786 M2P_Cfg2_SW_Ver_Byte16_02 "MBMU软件版本号最高字节Byte16对应ASCII码";
CM_ SG_ 2416176787 M2P_Cfg2_SW_Ver_Byte9_03 "MBMU软件版本号Byte9对应ASCII码";
CM_ SG_ 2416176787 M2P_Cfg2_SW_Ver_Byte10_03 "MBMU软件版本号Byte10对应ASCII码";
CM_ SG_ 2416176787 M2P_Cfg2_SW_Ver_Byte11_03 "MBMU软件版本号Byte11对应ASCII码";
CM_ SG_ 2416176787 M2P_Cfg2_SW_Ver_Byte12_03 "MBMU软件版本号Byte12对应ASCII码";
CM_ SG_ 2416176787 M2P_Cfg2_SW_Ver_Byte13_03 "MBMU软件版本号Byte13对应ASCII码";
CM_ SG_ 2416176787 M2P_Cfg2_SW_Ver_Byte14_03 "MBMU软件版本号Byte14对应ASCII码";
CM_ SG_ 2416176787 M2P_Cfg2_SW_Ver_Byte15_03 "MBMU软件版本号Byte15对应ASCII码";
CM_ SG_ 2416176787 M2P_Cfg2_SW_Ver_Byte16_03 "MBMU软件版本号最高字节Byte16对应ASCII码";
CM_ SG_ 2416176788 M2P_Cfg2_SW_Ver_Byte9_04 "MBMU软件版本号Byte9对应ASCII码";
CM_ SG_ 2416176788 M2P_Cfg2_SW_Ver_Byte10_04 "MBMU软件版本号Byte10对应ASCII码";
CM_ SG_ 2416176788 M2P_Cfg2_SW_Ver_Byte11_04 "MBMU软件版本号Byte11对应ASCII码";
CM_ SG_ 2416176788 M2P_Cfg2_SW_Ver_Byte12_04 "MBMU软件版本号Byte12对应ASCII码";
CM_ SG_ 2416176788 M2P_Cfg2_SW_Ver_Byte13_04 "MBMU软件版本号Byte13对应ASCII码";
CM_ SG_ 2416176788 M2P_Cfg2_SW_Ver_Byte14_04 "MBMU软件版本号Byte14对应ASCII码";
CM_ SG_ 2416176788 M2P_Cfg2_SW_Ver_Byte15_04 "MBMU软件版本号Byte15对应ASCII码";
CM_ SG_ 2416176788 M2P_Cfg2_SW_Ver_Byte16_04 "MBMU软件版本号最高字节Byte16对应ASCII码";
CM_ SG_ 2416176789 M2P_Cfg2_SW_Ver_Byte9_05 "MBMU软件版本号Byte9对应ASCII码";
CM_ SG_ 2416176789 M2P_Cfg2_SW_Ver_Byte10_05 "MBMU软件版本号Byte10对应ASCII码";
CM_ SG_ 2416176789 M2P_Cfg2_SW_Ver_Byte11_05 "MBMU软件版本号Byte11对应ASCII码";
CM_ SG_ 2416176789 M2P_Cfg2_SW_Ver_Byte12_05 "MBMU软件版本号Byte12对应ASCII码";
CM_ SG_ 2416176789 M2P_Cfg2_SW_Ver_Byte13_05 "MBMU软件版本号Byte13对应ASCII码";
CM_ SG_ 2416176789 M2P_Cfg2_SW_Ver_Byte14_05 "MBMU软件版本号Byte14对应ASCII码";
CM_ SG_ 2416176789 M2P_Cfg2_SW_Ver_Byte15_05 "MBMU软件版本号Byte15对应ASCII码";
CM_ SG_ 2416176789 M2P_Cfg2_SW_Ver_Byte16_05 "MBMU软件版本号最高字节Byte16对应ASCII码";
CM_ SG_ 2416176790 M2P_Cfg2_SW_Ver_Byte9_06 "MBMU软件版本号Byte9对应ASCII码";
CM_ SG_ 2416176790 M2P_Cfg2_SW_Ver_Byte10_06 "MBMU软件版本号Byte10对应ASCII码";
CM_ SG_ 2416176790 M2P_Cfg2_SW_Ver_Byte11_06 "MBMU软件版本号Byte11对应ASCII码";
CM_ SG_ 2416176790 M2P_Cfg2_SW_Ver_Byte12_06 "MBMU软件版本号Byte12对应ASCII码";
CM_ SG_ 2416176790 M2P_Cfg2_SW_Ver_Byte13_06 "MBMU软件版本号Byte13对应ASCII码";
CM_ SG_ 2416176790 M2P_Cfg2_SW_Ver_Byte14_06 "MBMU软件版本号Byte14对应ASCII码";
CM_ SG_ 2416176790 M2P_Cfg2_SW_Ver_Byte15_06 "MBMU软件版本号Byte15对应ASCII码";
CM_ SG_ 2416176790 M2P_Cfg2_SW_Ver_Byte16_06 "MBMU软件版本号最高字节Byte16对应ASCII码";
CM_ SG_ 2416176791 M2P_Cfg2_SW_Ver_Byte9_07 "MBMU软件版本号Byte9对应ASCII码";
CM_ SG_ 2416176791 M2P_Cfg2_SW_Ver_Byte10_07 "MBMU软件版本号Byte10对应ASCII码";
CM_ SG_ 2416176791 M2P_Cfg2_SW_Ver_Byte11_07 "MBMU软件版本号Byte11对应ASCII码";
CM_ SG_ 2416176791 M2P_Cfg2_SW_Ver_Byte12_07 "MBMU软件版本号Byte12对应ASCII码";
CM_ SG_ 2416176791 M2P_Cfg2_SW_Ver_Byte13_07 "MBMU软件版本号Byte13对应ASCII码";
CM_ SG_ 2416176791 M2P_Cfg2_SW_Ver_Byte14_07 "MBMU软件版本号Byte14对应ASCII码";
CM_ SG_ 2416176791 M2P_Cfg2_SW_Ver_Byte15_07 "MBMU软件版本号Byte15对应ASCII码";
CM_ SG_ 2416176791 M2P_Cfg2_SW_Ver_Byte16_07 "MBMU软件版本号最高字节Byte16对应ASCII码";
CM_ SG_ 2416176792 M2P_Cfg2_SW_Ver_Byte9_08 "MBMU软件版本号Byte9对应ASCII码";
CM_ SG_ 2416176792 M2P_Cfg2_SW_Ver_Byte10_08 "MBMU软件版本号Byte10对应ASCII码";
CM_ SG_ 2416176792 M2P_Cfg2_SW_Ver_Byte11_08 "MBMU软件版本号Byte11对应ASCII码";
CM_ SG_ 2416176792 M2P_Cfg2_SW_Ver_Byte12_08 "MBMU软件版本号Byte12对应ASCII码";
CM_ SG_ 2416176792 M2P_Cfg2_SW_Ver_Byte13_08 "MBMU软件版本号Byte13对应ASCII码";
CM_ SG_ 2416176792 M2P_Cfg2_SW_Ver_Byte14_08 "MBMU软件版本号Byte14对应ASCII码";
CM_ SG_ 2416176792 M2P_Cfg2_SW_Ver_Byte15_08 "MBMU软件版本号Byte15对应ASCII码";
CM_ SG_ 2416176792 M2P_Cfg2_SW_Ver_Byte16_08 "MBMU软件版本号最高字节Byte16对应ASCII码";
CM_ SG_ 2416176793 M2P_Cfg2_SW_Ver_Byte9_09 "MBMU软件版本号Byte9对应ASCII码";
CM_ SG_ 2416176793 M2P_Cfg2_SW_Ver_Byte10_09 "MBMU软件版本号Byte10对应ASCII码";
CM_ SG_ 2416176793 M2P_Cfg2_SW_Ver_Byte11_09 "MBMU软件版本号Byte11对应ASCII码";
CM_ SG_ 2416176793 M2P_Cfg2_SW_Ver_Byte12_09 "MBMU软件版本号Byte12对应ASCII码";
CM_ SG_ 2416176793 M2P_Cfg2_SW_Ver_Byte13_09 "MBMU软件版本号Byte13对应ASCII码";
CM_ SG_ 2416176793 M2P_Cfg2_SW_Ver_Byte14_09 "MBMU软件版本号Byte14对应ASCII码";
CM_ SG_ 2416176793 M2P_Cfg2_SW_Ver_Byte15_09 "MBMU软件版本号Byte15对应ASCII码";
CM_ SG_ 2416176793 M2P_Cfg2_SW_Ver_Byte16_09 "MBMU软件版本号最高字节Byte16对应ASCII码";
CM_ SG_ 2416176794 M2P_Cfg2_SW_Ver_Byte9_10 "MBMU软件版本号Byte9对应ASCII码";
CM_ SG_ 2416176794 M2P_Cfg2_SW_Ver_Byte10_10 "MBMU软件版本号Byte10对应ASCII码";
CM_ SG_ 2416176794 M2P_Cfg2_SW_Ver_Byte11_10 "MBMU软件版本号Byte11对应ASCII码";
CM_ SG_ 2416176794 M2P_Cfg2_SW_Ver_Byte12_10 "MBMU软件版本号Byte12对应ASCII码";
CM_ SG_ 2416176794 M2P_Cfg2_SW_Ver_Byte13_10 "MBMU软件版本号Byte13对应ASCII码";
CM_ SG_ 2416176794 M2P_Cfg2_SW_Ver_Byte14_10 "MBMU软件版本号Byte14对应ASCII码";
CM_ SG_ 2416176794 M2P_Cfg2_SW_Ver_Byte15_10 "MBMU软件版本号Byte15对应ASCII码";
CM_ SG_ 2416176794 M2P_Cfg2_SW_Ver_Byte16_10 "MBMU软件版本号最高字节Byte16对应ASCII码";
CM_ SG_ 2416176795 M2P_Cfg2_SW_Ver_Byte9_11 "MBMU软件版本号Byte9对应ASCII码";
CM_ SG_ 2416176795 M2P_Cfg2_SW_Ver_Byte10_11 "MBMU软件版本号Byte10对应ASCII码";
CM_ SG_ 2416176795 M2P_Cfg2_SW_Ver_Byte11_11 "MBMU软件版本号Byte11对应ASCII码";
CM_ SG_ 2416176795 M2P_Cfg2_SW_Ver_Byte12_11 "MBMU软件版本号Byte12对应ASCII码";
CM_ SG_ 2416176795 M2P_Cfg2_SW_Ver_Byte13_11 "MBMU软件版本号Byte13对应ASCII码";
CM_ SG_ 2416176795 M2P_Cfg2_SW_Ver_Byte14_11 "MBMU软件版本号Byte14对应ASCII码";
CM_ SG_ 2416176795 M2P_Cfg2_SW_Ver_Byte15_11 "MBMU软件版本号Byte15对应ASCII码";
CM_ SG_ 2416176795 M2P_Cfg2_SW_Ver_Byte16_11 "MBMU软件版本号最高字节Byte16对应ASCII码";
CM_ SG_ 2416176796 M2P_Cfg2_SW_Ver_Byte9_12 "MBMU软件版本号Byte9对应ASCII码";
CM_ SG_ 2416176796 M2P_Cfg2_SW_Ver_Byte10_12 "MBMU软件版本号Byte10对应ASCII码";
CM_ SG_ 2416176796 M2P_Cfg2_SW_Ver_Byte11_12 "MBMU软件版本号Byte11对应ASCII码";
CM_ SG_ 2416176796 M2P_Cfg2_SW_Ver_Byte12_12 "MBMU软件版本号Byte12对应ASCII码";
CM_ SG_ 2416176796 M2P_Cfg2_SW_Ver_Byte13_12 "MBMU软件版本号Byte13对应ASCII码";
CM_ SG_ 2416176796 M2P_Cfg2_SW_Ver_Byte14_12 "MBMU软件版本号Byte14对应ASCII码";
CM_ SG_ 2416176796 M2P_Cfg2_SW_Ver_Byte15_12 "MBMU软件版本号Byte15对应ASCII码";
CM_ SG_ 2416176796 M2P_Cfg2_SW_Ver_Byte16_12 "MBMU软件版本号最高字节Byte16对应ASCII码";
CM_ SG_ 2416176797 M2P_Cfg2_SW_Ver_Byte9_13 "MBMU软件版本号Byte9对应ASCII码";
CM_ SG_ 2416176797 M2P_Cfg2_SW_Ver_Byte10_13 "MBMU软件版本号Byte10对应ASCII码";
CM_ SG_ 2416176797 M2P_Cfg2_SW_Ver_Byte11_13 "MBMU软件版本号Byte11对应ASCII码";
CM_ SG_ 2416176797 M2P_Cfg2_SW_Ver_Byte12_13 "MBMU软件版本号Byte12对应ASCII码";
CM_ SG_ 2416176797 M2P_Cfg2_SW_Ver_Byte13_13 "MBMU软件版本号Byte13对应ASCII码";
CM_ SG_ 2416176797 M2P_Cfg2_SW_Ver_Byte14_13 "MBMU软件版本号Byte14对应ASCII码";
CM_ SG_ 2416176797 M2P_Cfg2_SW_Ver_Byte15_13 "MBMU软件版本号Byte15对应ASCII码";
CM_ SG_ 2416176797 M2P_Cfg2_SW_Ver_Byte16_13 "MBMU软件版本号最高字节Byte16对应ASCII码";
CM_ SG_ 2416176798 M2P_Cfg2_SW_Ver_Byte9_14 "MBMU软件版本号Byte9对应ASCII码";
CM_ SG_ 2416176798 M2P_Cfg2_SW_Ver_Byte10_14 "MBMU软件版本号Byte10对应ASCII码";
CM_ SG_ 2416176798 M2P_Cfg2_SW_Ver_Byte11_14 "MBMU软件版本号Byte11对应ASCII码";
CM_ SG_ 2416176798 M2P_Cfg2_SW_Ver_Byte12_14 "MBMU软件版本号Byte12对应ASCII码";
CM_ SG_ 2416176798 M2P_Cfg2_SW_Ver_Byte13_14 "MBMU软件版本号Byte13对应ASCII码";
CM_ SG_ 2416176798 M2P_Cfg2_SW_Ver_Byte14_14 "MBMU软件版本号Byte14对应ASCII码";
CM_ SG_ 2416176798 M2P_Cfg2_SW_Ver_Byte15_14 "MBMU软件版本号Byte15对应ASCII码";
CM_ SG_ 2416176798 M2P_Cfg2_SW_Ver_Byte16_14 "MBMU软件版本号最高字节Byte16对应ASCII码";
CM_ SG_ 2416176799 M2P_Cfg2_SW_Ver_Byte9_15 "MBMU软件版本号Byte9对应ASCII码";
CM_ SG_ 2416176799 M2P_Cfg2_SW_Ver_Byte10_15 "MBMU软件版本号Byte10对应ASCII码";
CM_ SG_ 2416176799 M2P_Cfg2_SW_Ver_Byte11_15 "MBMU软件版本号Byte11对应ASCII码";
CM_ SG_ 2416176799 M2P_Cfg2_SW_Ver_Byte12_15 "MBMU软件版本号Byte12对应ASCII码";
CM_ SG_ 2416176799 M2P_Cfg2_SW_Ver_Byte13_15 "MBMU软件版本号Byte13对应ASCII码";
CM_ SG_ 2416176799 M2P_Cfg2_SW_Ver_Byte14_15 "MBMU软件版本号Byte14对应ASCII码";
CM_ SG_ 2416176799 M2P_Cfg2_SW_Ver_Byte15_15 "MBMU软件版本号Byte15对应ASCII码";
CM_ SG_ 2416176799 M2P_Cfg2_SW_Ver_Byte16_15 "MBMU软件版本号最高字节Byte16对应ASCII码";
CM_ SG_ 2416176800 M2P_Cfg2_SW_Ver_Byte9_16 "MBMU软件版本号Byte9对应ASCII码";
CM_ SG_ 2416176800 M2P_Cfg2_SW_Ver_Byte10_16 "MBMU软件版本号Byte10对应ASCII码";
CM_ SG_ 2416176800 M2P_Cfg2_SW_Ver_Byte11_16 "MBMU软件版本号Byte11对应ASCII码";
CM_ SG_ 2416176800 M2P_Cfg2_SW_Ver_Byte12_16 "MBMU软件版本号Byte12对应ASCII码";
CM_ SG_ 2416176800 M2P_Cfg2_SW_Ver_Byte13_16 "MBMU软件版本号Byte13对应ASCII码";
CM_ SG_ 2416176800 M2P_Cfg2_SW_Ver_Byte14_16 "MBMU软件版本号Byte14对应ASCII码";
CM_ SG_ 2416176800 M2P_Cfg2_SW_Ver_Byte15_16 "MBMU软件版本号Byte15对应ASCII码";
CM_ SG_ 2416176800 M2P_Cfg2_SW_Ver_Byte16_16 "MBMU软件版本号最高字节Byte16对应ASCII码";
CM_ SG_ 2416176801 M2P_Cfg2_SW_Ver_Byte9_17 "MBMU软件版本号Byte9对应ASCII码";
CM_ SG_ 2416176801 M2P_Cfg2_SW_Ver_Byte10_17 "MBMU软件版本号Byte10对应ASCII码";
CM_ SG_ 2416176801 M2P_Cfg2_SW_Ver_Byte11_17 "MBMU软件版本号Byte11对应ASCII码";
CM_ SG_ 2416176801 M2P_Cfg2_SW_Ver_Byte12_17 "MBMU软件版本号Byte12对应ASCII码";
CM_ SG_ 2416176801 M2P_Cfg2_SW_Ver_Byte13_17 "MBMU软件版本号Byte13对应ASCII码";
CM_ SG_ 2416176801 M2P_Cfg2_SW_Ver_Byte14_17 "MBMU软件版本号Byte14对应ASCII码";
CM_ SG_ 2416176801 M2P_Cfg2_SW_Ver_Byte15_17 "MBMU软件版本号Byte15对应ASCII码";
CM_ SG_ 2416176801 M2P_Cfg2_SW_Ver_Byte16_17 "MBMU软件版本号最高字节Byte16对应ASCII码";
CM_ SG_ 2416176802 M2P_Cfg2_SW_Ver_Byte9_18 "MBMU软件版本号Byte9对应ASCII码";
CM_ SG_ 2416176802 M2P_Cfg2_SW_Ver_Byte10_18 "MBMU软件版本号Byte10对应ASCII码";
CM_ SG_ 2416176802 M2P_Cfg2_SW_Ver_Byte11_18 "MBMU软件版本号Byte11对应ASCII码";
CM_ SG_ 2416176802 M2P_Cfg2_SW_Ver_Byte12_18 "MBMU软件版本号Byte12对应ASCII码";
CM_ SG_ 2416176802 M2P_Cfg2_SW_Ver_Byte13_18 "MBMU软件版本号Byte13对应ASCII码";
CM_ SG_ 2416176802 M2P_Cfg2_SW_Ver_Byte14_18 "MBMU软件版本号Byte14对应ASCII码";
CM_ SG_ 2416176802 M2P_Cfg2_SW_Ver_Byte15_18 "MBMU软件版本号Byte15对应ASCII码";
CM_ SG_ 2416176802 M2P_Cfg2_SW_Ver_Byte16_18 "MBMU软件版本号最高字节Byte16对应ASCII码";
CM_ SG_ 2416176803 M2P_Cfg2_SW_Ver_Byte9_19 "MBMU软件版本号Byte9对应ASCII码";
CM_ SG_ 2416176803 M2P_Cfg2_SW_Ver_Byte10_19 "MBMU软件版本号Byte10对应ASCII码";
CM_ SG_ 2416176803 M2P_Cfg2_SW_Ver_Byte11_19 "MBMU软件版本号Byte11对应ASCII码";
CM_ SG_ 2416176803 M2P_Cfg2_SW_Ver_Byte12_19 "MBMU软件版本号Byte12对应ASCII码";
CM_ SG_ 2416176803 M2P_Cfg2_SW_Ver_Byte13_19 "MBMU软件版本号Byte13对应ASCII码";
CM_ SG_ 2416176803 M2P_Cfg2_SW_Ver_Byte14_19 "MBMU软件版本号Byte14对应ASCII码";
CM_ SG_ 2416176803 M2P_Cfg2_SW_Ver_Byte15_19 "MBMU软件版本号Byte15对应ASCII码";
CM_ SG_ 2416176803 M2P_Cfg2_SW_Ver_Byte16_19 "MBMU软件版本号最高字节Byte16对应ASCII码";
CM_ SG_ 2416176804 M2P_Cfg2_SW_Ver_Byte9_20 "MBMU软件版本号Byte9对应ASCII码";
CM_ SG_ 2416176804 M2P_Cfg2_SW_Ver_Byte10_20 "MBMU软件版本号Byte10对应ASCII码";
CM_ SG_ 2416176804 M2P_Cfg2_SW_Ver_Byte11_20 "MBMU软件版本号Byte11对应ASCII码";
CM_ SG_ 2416176804 M2P_Cfg2_SW_Ver_Byte12_20 "MBMU软件版本号Byte12对应ASCII码";
CM_ SG_ 2416176804 M2P_Cfg2_SW_Ver_Byte13_20 "MBMU软件版本号Byte13对应ASCII码";
CM_ SG_ 2416176804 M2P_Cfg2_SW_Ver_Byte14_20 "MBMU软件版本号Byte14对应ASCII码";
CM_ SG_ 2416176804 M2P_Cfg2_SW_Ver_Byte15_20 "MBMU软件版本号Byte15对应ASCII码";
CM_ SG_ 2416176804 M2P_Cfg2_SW_Ver_Byte16_20 "MBMU软件版本号最高字节Byte16对应ASCII码";
CM_ SG_ 2416176805 M2P_Cfg2_SW_Ver_Byte9_21 "MBMU软件版本号Byte9对应ASCII码";
CM_ SG_ 2416176805 M2P_Cfg2_SW_Ver_Byte10_21 "MBMU软件版本号Byte10对应ASCII码";
CM_ SG_ 2416176805 M2P_Cfg2_SW_Ver_Byte11_21 "MBMU软件版本号Byte11对应ASCII码";
CM_ SG_ 2416176805 M2P_Cfg2_SW_Ver_Byte12_21 "MBMU软件版本号Byte12对应ASCII码";
CM_ SG_ 2416176805 M2P_Cfg2_SW_Ver_Byte13_21 "MBMU软件版本号Byte13对应ASCII码";
CM_ SG_ 2416176805 M2P_Cfg2_SW_Ver_Byte14_21 "MBMU软件版本号Byte14对应ASCII码";
CM_ SG_ 2416176805 M2P_Cfg2_SW_Ver_Byte15_21 "MBMU软件版本号Byte15对应ASCII码";
CM_ SG_ 2416176805 M2P_Cfg2_SW_Ver_Byte16_21 "MBMU软件版本号最高字节Byte16对应ASCII码";
CM_ SG_ 2416176806 M2P_Cfg2_SW_Ver_Byte9_22 "MBMU软件版本号Byte9对应ASCII码";
CM_ SG_ 2416176806 M2P_Cfg2_SW_Ver_Byte10_22 "MBMU软件版本号Byte10对应ASCII码";
CM_ SG_ 2416176806 M2P_Cfg2_SW_Ver_Byte11_22 "MBMU软件版本号Byte11对应ASCII码";
CM_ SG_ 2416176806 M2P_Cfg2_SW_Ver_Byte12_22 "MBMU软件版本号Byte12对应ASCII码";
CM_ SG_ 2416176806 M2P_Cfg2_SW_Ver_Byte13_22 "MBMU软件版本号Byte13对应ASCII码";
CM_ SG_ 2416176806 M2P_Cfg2_SW_Ver_Byte14_22 "MBMU软件版本号Byte14对应ASCII码";
CM_ SG_ 2416176806 M2P_Cfg2_SW_Ver_Byte15_22 "MBMU软件版本号Byte15对应ASCII码";
CM_ SG_ 2416176806 M2P_Cfg2_SW_Ver_Byte16_22 "MBMU软件版本号最高字节Byte16对应ASCII码";
CM_ SG_ 2416176807 M2P_Cfg2_SW_Ver_Byte9_23 "MBMU软件版本号Byte9对应ASCII码";
CM_ SG_ 2416176807 M2P_Cfg2_SW_Ver_Byte10_23 "MBMU软件版本号Byte10对应ASCII码";
CM_ SG_ 2416176807 M2P_Cfg2_SW_Ver_Byte11_23 "MBMU软件版本号Byte11对应ASCII码";
CM_ SG_ 2416176807 M2P_Cfg2_SW_Ver_Byte12_23 "MBMU软件版本号Byte12对应ASCII码";
CM_ SG_ 2416176807 M2P_Cfg2_SW_Ver_Byte13_23 "MBMU软件版本号Byte13对应ASCII码";
CM_ SG_ 2416176807 M2P_Cfg2_SW_Ver_Byte14_23 "MBMU软件版本号Byte14对应ASCII码";
CM_ SG_ 2416176807 M2P_Cfg2_SW_Ver_Byte15_23 "MBMU软件版本号Byte15对应ASCII码";
CM_ SG_ 2416176807 M2P_Cfg2_SW_Ver_Byte16_23 "MBMU软件版本号最高字节Byte16对应ASCII码";
CM_ SG_ 2416176808 M2P_Cfg2_SW_Ver_Byte9_24 "MBMU软件版本号Byte9对应ASCII码";
CM_ SG_ 2416176808 M2P_Cfg2_SW_Ver_Byte10_24 "MBMU软件版本号Byte10对应ASCII码";
CM_ SG_ 2416176808 M2P_Cfg2_SW_Ver_Byte11_24 "MBMU软件版本号Byte11对应ASCII码";
CM_ SG_ 2416176808 M2P_Cfg2_SW_Ver_Byte12_24 "MBMU软件版本号Byte12对应ASCII码";
CM_ SG_ 2416176808 M2P_Cfg2_SW_Ver_Byte13_24 "MBMU软件版本号Byte13对应ASCII码";
CM_ SG_ 2416176808 M2P_Cfg2_SW_Ver_Byte14_24 "MBMU软件版本号Byte14对应ASCII码";
CM_ SG_ 2416176808 M2P_Cfg2_SW_Ver_Byte15_24 "MBMU软件版本号Byte15对应ASCII码";
CM_ SG_ 2416176808 M2P_Cfg2_SW_Ver_Byte16_24 "MBMU软件版本号最高字节Byte16对应ASCII码";
CM_ SG_ 2416176809 M2P_Cfg2_SW_Ver_Byte9_25 "MBMU软件版本号Byte9对应ASCII码";
CM_ SG_ 2416176809 M2P_Cfg2_SW_Ver_Byte10_25 "MBMU软件版本号Byte10对应ASCII码";
CM_ SG_ 2416176809 M2P_Cfg2_SW_Ver_Byte11_25 "MBMU软件版本号Byte11对应ASCII码";
CM_ SG_ 2416176809 M2P_Cfg2_SW_Ver_Byte12_25 "MBMU软件版本号Byte12对应ASCII码";
CM_ SG_ 2416176809 M2P_Cfg2_SW_Ver_Byte13_25 "MBMU软件版本号Byte13对应ASCII码";
CM_ SG_ 2416176809 M2P_Cfg2_SW_Ver_Byte14_25 "MBMU软件版本号Byte14对应ASCII码";
CM_ SG_ 2416176809 M2P_Cfg2_SW_Ver_Byte15_25 "MBMU软件版本号Byte15对应ASCII码";
CM_ SG_ 2416176809 M2P_Cfg2_SW_Ver_Byte16_25 "MBMU软件版本号最高字节Byte16对应ASCII码";
CM_ SG_ 2416176810 M2P_Cfg2_SW_Ver_Byte9_26 "MBMU软件版本号Byte9对应ASCII码";
CM_ SG_ 2416176810 M2P_Cfg2_SW_Ver_Byte10_26 "MBMU软件版本号Byte10对应ASCII码";
CM_ SG_ 2416176810 M2P_Cfg2_SW_Ver_Byte11_26 "MBMU软件版本号Byte11对应ASCII码";
CM_ SG_ 2416176810 M2P_Cfg2_SW_Ver_Byte12_26 "MBMU软件版本号Byte12对应ASCII码";
CM_ SG_ 2416176810 M2P_Cfg2_SW_Ver_Byte13_26 "MBMU软件版本号Byte13对应ASCII码";
CM_ SG_ 2416176810 M2P_Cfg2_SW_Ver_Byte14_26 "MBMU软件版本号Byte14对应ASCII码";
CM_ SG_ 2416176810 M2P_Cfg2_SW_Ver_Byte15_26 "MBMU软件版本号Byte15对应ASCII码";
CM_ SG_ 2416176810 M2P_Cfg2_SW_Ver_Byte16_26 "MBMU软件版本号最高字节Byte16对应ASCII码";
CM_ SG_ 2416176811 M2P_Cfg2_SW_Ver_Byte9_27 "MBMU软件版本号Byte9对应ASCII码";
CM_ SG_ 2416176811 M2P_Cfg2_SW_Ver_Byte10_27 "MBMU软件版本号Byte10对应ASCII码";
CM_ SG_ 2416176811 M2P_Cfg2_SW_Ver_Byte11_27 "MBMU软件版本号Byte11对应ASCII码";
CM_ SG_ 2416176811 M2P_Cfg2_SW_Ver_Byte12_27 "MBMU软件版本号Byte12对应ASCII码";
CM_ SG_ 2416176811 M2P_Cfg2_SW_Ver_Byte13_27 "MBMU软件版本号Byte13对应ASCII码";
CM_ SG_ 2416176811 M2P_Cfg2_SW_Ver_Byte14_27 "MBMU软件版本号Byte14对应ASCII码";
CM_ SG_ 2416176811 M2P_Cfg2_SW_Ver_Byte15_27 "MBMU软件版本号Byte15对应ASCII码";
CM_ SG_ 2416176811 M2P_Cfg2_SW_Ver_Byte16_27 "MBMU软件版本号最高字节Byte16对应ASCII码";
CM_ SG_ 2416176812 M2P_Cfg2_SW_Ver_Byte9_28 "MBMU软件版本号Byte9对应ASCII码";
CM_ SG_ 2416176812 M2P_Cfg2_SW_Ver_Byte10_28 "MBMU软件版本号Byte10对应ASCII码";
CM_ SG_ 2416176812 M2P_Cfg2_SW_Ver_Byte11_28 "MBMU软件版本号Byte11对应ASCII码";
CM_ SG_ 2416176812 M2P_Cfg2_SW_Ver_Byte12_28 "MBMU软件版本号Byte12对应ASCII码";
CM_ SG_ 2416176812 M2P_Cfg2_SW_Ver_Byte13_28 "MBMU软件版本号Byte13对应ASCII码";
CM_ SG_ 2416176812 M2P_Cfg2_SW_Ver_Byte14_28 "MBMU软件版本号Byte14对应ASCII码";
CM_ SG_ 2416176812 M2P_Cfg2_SW_Ver_Byte15_28 "MBMU软件版本号Byte15对应ASCII码";
CM_ SG_ 2416176812 M2P_Cfg2_SW_Ver_Byte16_28 "MBMU软件版本号最高字节Byte16对应ASCII码";
CM_ SG_ 2416176813 M2P_Cfg2_SW_Ver_Byte9_29 "MBMU软件版本号Byte9对应ASCII码";
CM_ SG_ 2416176813 M2P_Cfg2_SW_Ver_Byte10_29 "MBMU软件版本号Byte10对应ASCII码";
CM_ SG_ 2416176813 M2P_Cfg2_SW_Ver_Byte11_29 "MBMU软件版本号Byte11对应ASCII码";
CM_ SG_ 2416176813 M2P_Cfg2_SW_Ver_Byte12_29 "MBMU软件版本号Byte12对应ASCII码";
CM_ SG_ 2416176813 M2P_Cfg2_SW_Ver_Byte13_29 "MBMU软件版本号Byte13对应ASCII码";
CM_ SG_ 2416176813 M2P_Cfg2_SW_Ver_Byte14_29 "MBMU软件版本号Byte14对应ASCII码";
CM_ SG_ 2416176813 M2P_Cfg2_SW_Ver_Byte15_29 "MBMU软件版本号Byte15对应ASCII码";
CM_ SG_ 2416176813 M2P_Cfg2_SW_Ver_Byte16_29 "MBMU软件版本号最高字节Byte16对应ASCII码";
CM_ SG_ 2416176814 M2P_Cfg2_SW_Ver_Byte9_30 "MBMU软件版本号Byte9对应ASCII码";
CM_ SG_ 2416176814 M2P_Cfg2_SW_Ver_Byte10_30 "MBMU软件版本号Byte10对应ASCII码";
CM_ SG_ 2416176814 M2P_Cfg2_SW_Ver_Byte11_30 "MBMU软件版本号Byte11对应ASCII码";
CM_ SG_ 2416176814 M2P_Cfg2_SW_Ver_Byte12_30 "MBMU软件版本号Byte12对应ASCII码";
CM_ SG_ 2416176814 M2P_Cfg2_SW_Ver_Byte13_30 "MBMU软件版本号Byte13对应ASCII码";
CM_ SG_ 2416176814 M2P_Cfg2_SW_Ver_Byte14_30 "MBMU软件版本号Byte14对应ASCII码";
CM_ SG_ 2416176814 M2P_Cfg2_SW_Ver_Byte15_30 "MBMU软件版本号Byte15对应ASCII码";
CM_ SG_ 2416176814 M2P_Cfg2_SW_Ver_Byte16_30 "MBMU软件版本号最高字节Byte16对应ASCII码";
CM_ SG_ 2416176815 M2P_Cfg2_SW_Ver_Byte9_31 "MBMU软件版本号Byte9对应ASCII码";
CM_ SG_ 2416176815 M2P_Cfg2_SW_Ver_Byte10_31 "MBMU软件版本号Byte10对应ASCII码";
CM_ SG_ 2416176815 M2P_Cfg2_SW_Ver_Byte11_31 "MBMU软件版本号Byte11对应ASCII码";
CM_ SG_ 2416176815 M2P_Cfg2_SW_Ver_Byte12_31 "MBMU软件版本号Byte12对应ASCII码";
CM_ SG_ 2416176815 M2P_Cfg2_SW_Ver_Byte13_31 "MBMU软件版本号Byte13对应ASCII码";
CM_ SG_ 2416176815 M2P_Cfg2_SW_Ver_Byte14_31 "MBMU软件版本号Byte14对应ASCII码";
CM_ SG_ 2416176815 M2P_Cfg2_SW_Ver_Byte15_31 "MBMU软件版本号Byte15对应ASCII码";
CM_ SG_ 2416176815 M2P_Cfg2_SW_Ver_Byte16_31 "MBMU软件版本号最高字节Byte16对应ASCII码";
CM_ SG_ 2416242321 M2P_Cfg3_HW_Ver_Byte1_01 "MBMU硬件版本号最低字节Byte1对应ASCII码";
CM_ SG_ 2416242321 M2P_Cfg3_HW_Ver_Byte2_01 "MBMU硬件版本号Byte2对应ASCII码";
CM_ SG_ 2416242321 M2P_Cfg3_HW_Ver_Byte3_01 "MBMU硬件版本号Byte3对应ASCII码";
CM_ SG_ 2416242321 M2P_Cfg3_HW_Ver_Byte4_01 "MBMU硬件版本号Byte4对应ASCII码";
CM_ SG_ 2416242321 M2P_Cfg3_HW_Ver_Byte5_01 "MBMU硬件版本号Byte5对应ASCII码";
CM_ SG_ 2416242321 M2P_Cfg3_HW_Ver_Byte6_01 "MBMU硬件版本号Byte6对应ASCII码";
CM_ SG_ 2416242321 M2P_Cfg3_HW_Ver_Byte7_01 "MBMU硬件版本号Byte7对应ASCII码";
CM_ SG_ 2416242321 M2P_Cfg3_HW_Ver_Byte8_01 "MBMU硬件版本号Byte8对应ASCII码";
CM_ SG_ 2416242322 M2P_Cfg3_HW_Ver_Byte1_02 "MBMU硬件版本号最低字节Byte1对应ASCII码";
CM_ SG_ 2416242322 M2P_Cfg3_HW_Ver_Byte2_02 "MBMU硬件版本号Byte2对应ASCII码";
CM_ SG_ 2416242322 M2P_Cfg3_HW_Ver_Byte3_02 "MBMU硬件版本号Byte3对应ASCII码";
CM_ SG_ 2416242322 M2P_Cfg3_HW_Ver_Byte4_02 "MBMU硬件版本号Byte4对应ASCII码";
CM_ SG_ 2416242322 M2P_Cfg3_HW_Ver_Byte5_02 "MBMU硬件版本号Byte5对应ASCII码";
CM_ SG_ 2416242322 M2P_Cfg3_HW_Ver_Byte6_02 "MBMU硬件版本号Byte6对应ASCII码";
CM_ SG_ 2416242322 M2P_Cfg3_HW_Ver_Byte7_02 "MBMU硬件版本号Byte7对应ASCII码";
CM_ SG_ 2416242322 M2P_Cfg3_HW_Ver_Byte8_02 "MBMU硬件版本号Byte8对应ASCII码";
CM_ SG_ 2416242323 M2P_Cfg3_HW_Ver_Byte1_03 "MBMU硬件版本号最低字节Byte1对应ASCII码";
CM_ SG_ 2416242323 M2P_Cfg3_HW_Ver_Byte2_03 "MBMU硬件版本号Byte2对应ASCII码";
CM_ SG_ 2416242323 M2P_Cfg3_HW_Ver_Byte3_03 "MBMU硬件版本号Byte3对应ASCII码";
CM_ SG_ 2416242323 M2P_Cfg3_HW_Ver_Byte4_03 "MBMU硬件版本号Byte4对应ASCII码";
CM_ SG_ 2416242323 M2P_Cfg3_HW_Ver_Byte5_03 "MBMU硬件版本号Byte5对应ASCII码";
CM_ SG_ 2416242323 M2P_Cfg3_HW_Ver_Byte6_03 "MBMU硬件版本号Byte6对应ASCII码";
CM_ SG_ 2416242323 M2P_Cfg3_HW_Ver_Byte7_03 "MBMU硬件版本号Byte7对应ASCII码";
CM_ SG_ 2416242323 M2P_Cfg3_HW_Ver_Byte8_03 "MBMU硬件版本号Byte8对应ASCII码";
CM_ SG_ 2416242324 M2P_Cfg3_HW_Ver_Byte1_04 "MBMU硬件版本号最低字节Byte1对应ASCII码";
CM_ SG_ 2416242324 M2P_Cfg3_HW_Ver_Byte2_04 "MBMU硬件版本号Byte2对应ASCII码";
CM_ SG_ 2416242324 M2P_Cfg3_HW_Ver_Byte3_04 "MBMU硬件版本号Byte3对应ASCII码";
CM_ SG_ 2416242324 M2P_Cfg3_HW_Ver_Byte4_04 "MBMU硬件版本号Byte4对应ASCII码";
CM_ SG_ 2416242324 M2P_Cfg3_HW_Ver_Byte5_04 "MBMU硬件版本号Byte5对应ASCII码";
CM_ SG_ 2416242324 M2P_Cfg3_HW_Ver_Byte6_04 "MBMU硬件版本号Byte6对应ASCII码";
CM_ SG_ 2416242324 M2P_Cfg3_HW_Ver_Byte7_04 "MBMU硬件版本号Byte7对应ASCII码";
CM_ SG_ 2416242324 M2P_Cfg3_HW_Ver_Byte8_04 "MBMU硬件版本号Byte8对应ASCII码";
CM_ SG_ 2416242325 M2P_Cfg3_HW_Ver_Byte1_05 "MBMU硬件版本号最低字节Byte1对应ASCII码";
CM_ SG_ 2416242325 M2P_Cfg3_HW_Ver_Byte2_05 "MBMU硬件版本号Byte2对应ASCII码";
CM_ SG_ 2416242325 M2P_Cfg3_HW_Ver_Byte3_05 "MBMU硬件版本号Byte3对应ASCII码";
CM_ SG_ 2416242325 M2P_Cfg3_HW_Ver_Byte4_05 "MBMU硬件版本号Byte4对应ASCII码";
CM_ SG_ 2416242325 M2P_Cfg3_HW_Ver_Byte5_05 "MBMU硬件版本号Byte5对应ASCII码";
CM_ SG_ 2416242325 M2P_Cfg3_HW_Ver_Byte6_05 "MBMU硬件版本号Byte6对应ASCII码";
CM_ SG_ 2416242325 M2P_Cfg3_HW_Ver_Byte7_05 "MBMU硬件版本号Byte7对应ASCII码";
CM_ SG_ 2416242325 M2P_Cfg3_HW_Ver_Byte8_05 "MBMU硬件版本号Byte8对应ASCII码";
CM_ SG_ 2416242326 M2P_Cfg3_HW_Ver_Byte1_06 "MBMU硬件版本号最低字节Byte1对应ASCII码";
CM_ SG_ 2416242326 M2P_Cfg3_HW_Ver_Byte2_06 "MBMU硬件版本号Byte2对应ASCII码";
CM_ SG_ 2416242326 M2P_Cfg3_HW_Ver_Byte3_06 "MBMU硬件版本号Byte3对应ASCII码";
CM_ SG_ 2416242326 M2P_Cfg3_HW_Ver_Byte4_06 "MBMU硬件版本号Byte4对应ASCII码";
CM_ SG_ 2416242326 M2P_Cfg3_HW_Ver_Byte5_06 "MBMU硬件版本号Byte5对应ASCII码";
CM_ SG_ 2416242326 M2P_Cfg3_HW_Ver_Byte6_06 "MBMU硬件版本号Byte6对应ASCII码";
CM_ SG_ 2416242326 M2P_Cfg3_HW_Ver_Byte7_06 "MBMU硬件版本号Byte7对应ASCII码";
CM_ SG_ 2416242326 M2P_Cfg3_HW_Ver_Byte8_06 "MBMU硬件版本号Byte8对应ASCII码";
CM_ SG_ 2416242327 M2P_Cfg3_HW_Ver_Byte1_07 "MBMU硬件版本号最低字节Byte1对应ASCII码";
CM_ SG_ 2416242327 M2P_Cfg3_HW_Ver_Byte2_07 "MBMU硬件版本号Byte2对应ASCII码";
CM_ SG_ 2416242327 M2P_Cfg3_HW_Ver_Byte3_07 "MBMU硬件版本号Byte3对应ASCII码";
CM_ SG_ 2416242327 M2P_Cfg3_HW_Ver_Byte4_07 "MBMU硬件版本号Byte4对应ASCII码";
CM_ SG_ 2416242327 M2P_Cfg3_HW_Ver_Byte5_07 "MBMU硬件版本号Byte5对应ASCII码";
CM_ SG_ 2416242327 M2P_Cfg3_HW_Ver_Byte6_07 "MBMU硬件版本号Byte6对应ASCII码";
CM_ SG_ 2416242327 M2P_Cfg3_HW_Ver_Byte7_07 "MBMU硬件版本号Byte7对应ASCII码";
CM_ SG_ 2416242327 M2P_Cfg3_HW_Ver_Byte8_07 "MBMU硬件版本号Byte8对应ASCII码";
CM_ SG_ 2416242328 M2P_Cfg3_HW_Ver_Byte1_08 "MBMU硬件版本号最低字节Byte1对应ASCII码";
CM_ SG_ 2416242328 M2P_Cfg3_HW_Ver_Byte2_08 "MBMU硬件版本号Byte2对应ASCII码";
CM_ SG_ 2416242328 M2P_Cfg3_HW_Ver_Byte3_08 "MBMU硬件版本号Byte3对应ASCII码";
CM_ SG_ 2416242328 M2P_Cfg3_HW_Ver_Byte4_08 "MBMU硬件版本号Byte4对应ASCII码";
CM_ SG_ 2416242328 M2P_Cfg3_HW_Ver_Byte5_08 "MBMU硬件版本号Byte5对应ASCII码";
CM_ SG_ 2416242328 M2P_Cfg3_HW_Ver_Byte6_08 "MBMU硬件版本号Byte6对应ASCII码";
CM_ SG_ 2416242328 M2P_Cfg3_HW_Ver_Byte7_08 "MBMU硬件版本号Byte7对应ASCII码";
CM_ SG_ 2416242328 M2P_Cfg3_HW_Ver_Byte8_08 "MBMU硬件版本号Byte8对应ASCII码";
CM_ SG_ 2416242329 M2P_Cfg3_HW_Ver_Byte1_09 "MBMU硬件版本号最低字节Byte1对应ASCII码";
CM_ SG_ 2416242329 M2P_Cfg3_HW_Ver_Byte2_09 "MBMU硬件版本号Byte2对应ASCII码";
CM_ SG_ 2416242329 M2P_Cfg3_HW_Ver_Byte3_09 "MBMU硬件版本号Byte3对应ASCII码";
CM_ SG_ 2416242329 M2P_Cfg3_HW_Ver_Byte4_09 "MBMU硬件版本号Byte4对应ASCII码";
CM_ SG_ 2416242329 M2P_Cfg3_HW_Ver_Byte5_09 "MBMU硬件版本号Byte5对应ASCII码";
CM_ SG_ 2416242329 M2P_Cfg3_HW_Ver_Byte6_09 "MBMU硬件版本号Byte6对应ASCII码";
CM_ SG_ 2416242329 M2P_Cfg3_HW_Ver_Byte7_09 "MBMU硬件版本号Byte7对应ASCII码";
CM_ SG_ 2416242329 M2P_Cfg3_HW_Ver_Byte8_09 "MBMU硬件版本号Byte8对应ASCII码";
CM_ SG_ 2416242330 M2P_Cfg3_HW_Ver_Byte1_10 "MBMU硬件版本号最低字节Byte1对应ASCII码";
CM_ SG_ 2416242330 M2P_Cfg3_HW_Ver_Byte2_10 "MBMU硬件版本号Byte2对应ASCII码";
CM_ SG_ 2416242330 M2P_Cfg3_HW_Ver_Byte3_10 "MBMU硬件版本号Byte3对应ASCII码";
CM_ SG_ 2416242330 M2P_Cfg3_HW_Ver_Byte4_10 "MBMU硬件版本号Byte4对应ASCII码";
CM_ SG_ 2416242330 M2P_Cfg3_HW_Ver_Byte5_10 "MBMU硬件版本号Byte5对应ASCII码";
CM_ SG_ 2416242330 M2P_Cfg3_HW_Ver_Byte6_10 "MBMU硬件版本号Byte6对应ASCII码";
CM_ SG_ 2416242330 M2P_Cfg3_HW_Ver_Byte7_10 "MBMU硬件版本号Byte7对应ASCII码";
CM_ SG_ 2416242330 M2P_Cfg3_HW_Ver_Byte8_10 "MBMU硬件版本号Byte8对应ASCII码";
CM_ SG_ 2416242331 M2P_Cfg3_HW_Ver_Byte1_11 "MBMU硬件版本号最低字节Byte1对应ASCII码";
CM_ SG_ 2416242331 M2P_Cfg3_HW_Ver_Byte2_11 "MBMU硬件版本号Byte2对应ASCII码";
CM_ SG_ 2416242331 M2P_Cfg3_HW_Ver_Byte3_11 "MBMU硬件版本号Byte3对应ASCII码";
CM_ SG_ 2416242331 M2P_Cfg3_HW_Ver_Byte4_11 "MBMU硬件版本号Byte4对应ASCII码";
CM_ SG_ 2416242331 M2P_Cfg3_HW_Ver_Byte5_11 "MBMU硬件版本号Byte5对应ASCII码";
CM_ SG_ 2416242331 M2P_Cfg3_HW_Ver_Byte6_11 "MBMU硬件版本号Byte6对应ASCII码";
CM_ SG_ 2416242331 M2P_Cfg3_HW_Ver_Byte7_11 "MBMU硬件版本号Byte7对应ASCII码";
CM_ SG_ 2416242331 M2P_Cfg3_HW_Ver_Byte8_11 "MBMU硬件版本号Byte8对应ASCII码";
CM_ SG_ 2416242332 M2P_Cfg3_HW_Ver_Byte1_12 "MBMU硬件版本号最低字节Byte1对应ASCII码";
CM_ SG_ 2416242332 M2P_Cfg3_HW_Ver_Byte2_12 "MBMU硬件版本号Byte2对应ASCII码";
CM_ SG_ 2416242332 M2P_Cfg3_HW_Ver_Byte3_12 "MBMU硬件版本号Byte3对应ASCII码";
CM_ SG_ 2416242332 M2P_Cfg3_HW_Ver_Byte4_12 "MBMU硬件版本号Byte4对应ASCII码";
CM_ SG_ 2416242332 M2P_Cfg3_HW_Ver_Byte5_12 "MBMU硬件版本号Byte5对应ASCII码";
CM_ SG_ 2416242332 M2P_Cfg3_HW_Ver_Byte6_12 "MBMU硬件版本号Byte6对应ASCII码";
CM_ SG_ 2416242332 M2P_Cfg3_HW_Ver_Byte7_12 "MBMU硬件版本号Byte7对应ASCII码";
CM_ SG_ 2416242332 M2P_Cfg3_HW_Ver_Byte8_12 "MBMU硬件版本号Byte8对应ASCII码";
CM_ SG_ 2416242333 M2P_Cfg3_HW_Ver_Byte1_13 "MBMU硬件版本号最低字节Byte1对应ASCII码";
CM_ SG_ 2416242333 M2P_Cfg3_HW_Ver_Byte2_13 "MBMU硬件版本号Byte2对应ASCII码";
CM_ SG_ 2416242333 M2P_Cfg3_HW_Ver_Byte3_13 "MBMU硬件版本号Byte3对应ASCII码";
CM_ SG_ 2416242333 M2P_Cfg3_HW_Ver_Byte4_13 "MBMU硬件版本号Byte4对应ASCII码";
CM_ SG_ 2416242333 M2P_Cfg3_HW_Ver_Byte5_13 "MBMU硬件版本号Byte5对应ASCII码";
CM_ SG_ 2416242333 M2P_Cfg3_HW_Ver_Byte6_13 "MBMU硬件版本号Byte6对应ASCII码";
CM_ SG_ 2416242333 M2P_Cfg3_HW_Ver_Byte7_13 "MBMU硬件版本号Byte7对应ASCII码";
CM_ SG_ 2416242333 M2P_Cfg3_HW_Ver_Byte8_13 "MBMU硬件版本号Byte8对应ASCII码";
CM_ SG_ 2416242334 M2P_Cfg3_HW_Ver_Byte1_14 "MBMU硬件版本号最低字节Byte1对应ASCII码";
CM_ SG_ 2416242334 M2P_Cfg3_HW_Ver_Byte2_14 "MBMU硬件版本号Byte2对应ASCII码";
CM_ SG_ 2416242334 M2P_Cfg3_HW_Ver_Byte3_14 "MBMU硬件版本号Byte3对应ASCII码";
CM_ SG_ 2416242334 M2P_Cfg3_HW_Ver_Byte4_14 "MBMU硬件版本号Byte4对应ASCII码";
CM_ SG_ 2416242334 M2P_Cfg3_HW_Ver_Byte5_14 "MBMU硬件版本号Byte5对应ASCII码";
CM_ SG_ 2416242334 M2P_Cfg3_HW_Ver_Byte6_14 "MBMU硬件版本号Byte6对应ASCII码";
CM_ SG_ 2416242334 M2P_Cfg3_HW_Ver_Byte7_14 "MBMU硬件版本号Byte7对应ASCII码";
CM_ SG_ 2416242334 M2P_Cfg3_HW_Ver_Byte8_14 "MBMU硬件版本号Byte8对应ASCII码";
CM_ SG_ 2416242335 M2P_Cfg3_HW_Ver_Byte1_15 "MBMU硬件版本号最低字节Byte1对应ASCII码";
CM_ SG_ 2416242335 M2P_Cfg3_HW_Ver_Byte2_15 "MBMU硬件版本号Byte2对应ASCII码";
CM_ SG_ 2416242335 M2P_Cfg3_HW_Ver_Byte3_15 "MBMU硬件版本号Byte3对应ASCII码";
CM_ SG_ 2416242335 M2P_Cfg3_HW_Ver_Byte4_15 "MBMU硬件版本号Byte4对应ASCII码";
CM_ SG_ 2416242335 M2P_Cfg3_HW_Ver_Byte5_15 "MBMU硬件版本号Byte5对应ASCII码";
CM_ SG_ 2416242335 M2P_Cfg3_HW_Ver_Byte6_15 "MBMU硬件版本号Byte6对应ASCII码";
CM_ SG_ 2416242335 M2P_Cfg3_HW_Ver_Byte7_15 "MBMU硬件版本号Byte7对应ASCII码";
CM_ SG_ 2416242335 M2P_Cfg3_HW_Ver_Byte8_15 "MBMU硬件版本号Byte8对应ASCII码";
CM_ SG_ 2416242336 M2P_Cfg3_HW_Ver_Byte1_16 "MBMU硬件版本号最低字节Byte1对应ASCII码";
CM_ SG_ 2416242336 M2P_Cfg3_HW_Ver_Byte2_16 "MBMU硬件版本号Byte2对应ASCII码";
CM_ SG_ 2416242336 M2P_Cfg3_HW_Ver_Byte3_16 "MBMU硬件版本号Byte3对应ASCII码";
CM_ SG_ 2416242336 M2P_Cfg3_HW_Ver_Byte4_16 "MBMU硬件版本号Byte4对应ASCII码";
CM_ SG_ 2416242336 M2P_Cfg3_HW_Ver_Byte5_16 "MBMU硬件版本号Byte5对应ASCII码";
CM_ SG_ 2416242336 M2P_Cfg3_HW_Ver_Byte6_16 "MBMU硬件版本号Byte6对应ASCII码";
CM_ SG_ 2416242336 M2P_Cfg3_HW_Ver_Byte7_16 "MBMU硬件版本号Byte7对应ASCII码";
CM_ SG_ 2416242336 M2P_Cfg3_HW_Ver_Byte8_16 "MBMU硬件版本号Byte8对应ASCII码";
VAL_ 2332552875 M2P_SysremainEngy_Charge_27 65535 "Invalid" ;
VAL_ 2332552875 M2P_SysremainEngy_DisCharge_27 65535 "Invalid" ;
VAL_ 2332552875 M2P_SOE_Charge_27 1023 "Invalid" ;
VAL_ 2332552875 M2P_SOE_Discharge_27 1023 "Invalid" ;
VAL_ 2332552876 M2P_SysremainEngy_Charge_28 65535 "Invalid" ;
VAL_ 2332552876 M2P_SysremainEngy_DisCharge_28 65535 "Invalid" ;
VAL_ 2332552876 M2P_SOE_Charge_28 1023 "Invalid" ;
VAL_ 2332552876 M2P_SOE_Discharge_28 1023 "Invalid" ;
VAL_ 2332552877 M2P_SysremainEngy_Charge_29 65535 "Invalid" ;
VAL_ 2332552877 M2P_SysremainEngy_DisCharge_29 65535 "Invalid" ;
VAL_ 2332552877 M2P_SOE_Charge_29 1023 "Invalid" ;
VAL_ 2332552877 M2P_SOE_Discharge_29 1023 "Invalid" ;
VAL_ 2332552878 M2P_SysremainEngy_Charge_30 65535 "Invalid" ;
VAL_ 2332552878 M2P_SysremainEngy_DisCharge_30 65535 "Invalid" ;
VAL_ 2332552878 M2P_SOE_Charge_30 1023 "Invalid" ;
VAL_ 2332552878 M2P_SOE_Discharge_30 1023 "Invalid" ;
VAL_ 2332552879 M2P_SysremainEngy_Charge_31 65535 "Invalid" ;
VAL_ 2332552879 M2P_SysremainEngy_DisCharge_31 65535 "Invalid" ;
VAL_ 2332552879 M2P_SOE_Charge_31 1023 "Invalid" ;
VAL_ 2332552879 M2P_SOE_Discharge_31 1023 "Invalid" ;
VAL_ 2415980177 M2P_Response_Byte1_01 0 "Write fail" 1 "写配置信息成功" 2 "写阈值成功" 3 "编码CAN地址" 4 "编码485地址" 5 "校准RTC时间" ;
VAL_ 2415980178 M2P_Response_Byte1_02 0 "Write fail" 1 "写配置信息成功" 2 "写阈值成功" 3 "编码CAN地址" 4 "编码485地址" 5 "校准RTC时间" ;
VAL_ 2415980179 M2P_Response_Byte1_03 0 "Write fail" 1 "写配置信息成功" 2 "写阈值成功" 3 "编码CAN地址" 4 "编码485地址" 5 "校准RTC时间" ;
VAL_ 2415980180 M2P_Response_Byte1_04 0 "Write fail" 1 "写配置信息成功" 2 "写阈值成功" 3 "编码CAN地址" 4 "编码485地址" 5 "校准RTC时间" ;
VAL_ 2415980181 M2P_Response_Byte1_05 0 "Write fail" 1 "写配置信息成功" 2 "写阈值成功" 3 "编码CAN地址" 4 "编码485地址" 5 "校准RTC时间" ;
VAL_ 2415980182 M2P_Response_Byte1_06 0 "Write fail" 1 "写配置信息成功" 2 "写阈值成功" 3 "编码CAN地址" 4 "编码485地址" 5 "校准RTC时间" ;
VAL_ 2415980183 M2P_Response_Byte1_07 0 "Write fail" 1 "写配置信息成功" 2 "写阈值成功" 3 "编码CAN地址" 4 "编码485地址" 5 "校准RTC时间" ;
VAL_ 2415980184 M2P_Response_Byte1_08 0 "Write fail" 1 "写配置信息成功" 2 "写阈值成功" 3 "编码CAN地址" 4 "编码485地址" 5 "校准RTC时间" ;
VAL_ 2415980185 M2P_Response_Byte1_09 0 "Write fail" 1 "写配置信息成功" 2 "写阈值成功" 3 "编码CAN地址" 4 "编码485地址" 5 "校准RTC时间" ;
VAL_ 2415980186 M2P_Response_Byte1_10 0 "Write fail" 1 "写配置信息成功" 2 "写阈值成功" 3 "编码CAN地址" 4 "编码485地址" 5 "校准RTC时间" ;
VAL_ 2415980187 M2P_Response_Byte1_11 0 "Write fail" 1 "写配置信息成功" 2 "写阈值成功" 3 "编码CAN地址" 4 "编码485地址" 5 "校准RTC时间" ;
VAL_ 2415980188 M2P_Response_Byte1_12 0 "Write fail" 1 "写配置信息成功" 2 "写阈值成功" 3 "编码CAN地址" 4 "编码485地址" 5 "校准RTC时间" ;
VAL_ 2415980189 M2P_Response_Byte1_13 0 "Write fail" 1 "写配置信息成功" 2 "写阈值成功" 3 "编码CAN地址" 4 "编码485地址" 5 "校准RTC时间" ;
VAL_ 2415980190 M2P_Response_Byte1_14 0 "Write fail" 1 "写配置信息成功" 2 "写阈值成功" 3 "编码CAN地址" 4 "编码485地址" 5 "校准RTC时间" ;
VAL_ 2415980191 M2P_Response_Byte1_15 0 "Write fail" 1 "写配置信息成功" 2 "写阈值成功" 3 "编码CAN地址" 4 "编码485地址" 5 "校准RTC时间" ;
VAL_ 2415980192 M2P_Response_Byte1_16 0 "Write fail" 1 "写配置信息成功" 2 "写阈值成功" 3 "编码CAN地址" 4 "编码485地址" 5 "校准RTC时间" ;
VAL_ 2415980193 M2P_Response_Byte1_17 0 "Write fail" 1 "写配置信息成功" 2 "写阈值成功" 3 "编码CAN地址" 4 "编码485地址" 5 "校准RTC时间" ;
VAL_ 2415980194 M2P_Response_Byte1_18 0 "Write fail" 1 "写配置信息成功" 2 "写阈值成功" 3 "编码CAN地址" 4 "编码485地址" 5 "校准RTC时间" ;
VAL_ 2415980195 M2P_Response_Byte1_19 0 "Write fail" 1 "写配置信息成功" 2 "写阈值成功" 3 "编码CAN地址" 4 "编码485地址" 5 "校准RTC时间" ;
VAL_ 2415980196 M2P_Response_Byte1_20 0 "Write fail" 1 "写配置信息成功" 2 "写阈值成功" 3 "编码CAN地址" 4 "编码485地址" 5 "校准RTC时间" ;
VAL_ 2415980197 M2P_Response_Byte1_21 0 "Write fail" 1 "写配置信息成功" 2 "写阈值成功" 3 "编码CAN地址" 4 "编码485地址" 5 "校准RTC时间" ;
VAL_ 2415980198 M2P_Response_Byte1_22 0 "Write fail" 1 "写配置信息成功" 2 "写阈值成功" 3 "编码CAN地址" 4 "编码485地址" 5 "校准RTC时间" ;
VAL_ 2415980199 M2P_Response_Byte1_23 0 "Write fail" 1 "写配置信息成功" 2 "写阈值成功" 3 "编码CAN地址" 4 "编码485地址" 5 "校准RTC时间" ;
VAL_ 2415980200 M2P_Response_Byte1_24 0 "Write fail" 1 "写配置信息成功" 2 "写阈值成功" 3 "编码CAN地址" 4 "编码485地址" 5 "校准RTC时间" ;
VAL_ 2415980201 M2P_Response_Byte1_25 0 "Write fail" 1 "写配置信息成功" 2 "写阈值成功" 3 "编码CAN地址" 4 "编码485地址" 5 "校准RTC时间" ;
VAL_ 2415980202 M2P_Response_Byte1_26 0 "Write fail" 1 "写配置信息成功" 2 "写阈值成功" 3 "编码CAN地址" 4 "编码485地址" 5 "校准RTC时间" ;
VAL_ 2415980203 M2P_Response_Byte1_27 0 "Write fail" 1 "写配置信息成功" 2 "写阈值成功" 3 "编码CAN地址" 4 "编码485地址" 5 "校准RTC时间" ;
VAL_ 2415980204 M2P_Response_Byte1_28 0 "Write fail" 1 "写配置信息成功" 2 "写阈值成功" 3 "编码CAN地址" 4 "编码485地址" 5 "校准RTC时间" ;
VAL_ 2415980205 M2P_Response_Byte1_29 0 "Write fail" 1 "写配置信息成功" 2 "写阈值成功" 3 "编码CAN地址" 4 "编码485地址" 5 "校准RTC时间" ;
VAL_ 2415980206 M2P_Response_Byte1_30 0 "Write fail" 1 "写配置信息成功" 2 "写阈值成功" 3 "编码CAN地址" 4 "编码485地址" 5 "校准RTC时间" ;
VAL_ 2415980207 M2P_Response_Byte1_31 0 "Write fail" 1 "写配置信息成功" 2 "写阈值成功" 3 "编码CAN地址" 4 "编码485地址" 5 "校准RTC时间" ;
VAL_ 2416045713 M2P_DIAG_BYTE1_01 0 "Nvm data" ;
VAL_ 2416045713 M2P_DIAG_BYTE2_01 0 "Max vol_1: " 1 "Max vol_2: " 2 "Max vol_3: " 3 "Min vol_1:" 4 "Min vol_2: " 5 "Min vol_3: " 6 "Max temp_1: " 7 "Max temp_2:" 8 "Max  temp_3:" 9 "Min temp_1: " 10 "Min  temp_2: " 11 "Min  temp_3: " 12 "Max chg cur_1: " 13 "Max chg cur_2: " 14 "Max chg cur_3: " 15 "Max dchg cur_1:" 16 "Max dchg cur_2: " 17 "Max dchg cur_3: " 18 "Min iso_1: " 19 "Min iso_2:" 20 "Min iso_3:" 21 "His alarm_1: " 22 "His alarm_2: " 23 "His alarm_3: " 24 "His alarm_4: " 25 "His alarm_5: " 26 "His alarm_6: " ;
VAL_ 2416045714 M2P_DIAG_BYTE1_02 0 "Nvm data" ;
VAL_ 2416045714 M2P_DIAG_BYTE2_02 0 "Max vol_1: " 1 "Max vol_2: " 2 "Max vol_3: " 3 "Min vol_1:" 4 "Min vol_2: " 5 "Min vol_3: " 6 "Max temp_1: " 7 "Max temp_2:" 8 "Max  temp_3:" 9 "Min temp_1: " 10 "Min  temp_2: " 11 "Min  temp_3: " 12 "Max chg cur_1: " 13 "Max chg cur_2: " 14 "Max chg cur_3: " 15 "Max dchg cur_1:" 16 "Max dchg cur_2: " 17 "Max dchg cur_3: " 18 "Min iso_1: " 19 "Min iso_2:" 20 "Min iso_3:" 21 "His alarm_1: " 22 "His alarm_2: " 23 "His alarm_3: " 24 "His alarm_4: " 25 "His alarm_5: " 26 "His alarm_6: " ;
VAL_ 2416045715 M2P_DIAG_BYTE1_03 0 "Nvm data" ;
VAL_ 2416045715 M2P_DIAG_BYTE2_03 0 "Max vol_1: " 1 "Max vol_2: " 2 "Max vol_3: " 3 "Min vol_1:" 4 "Min vol_2: " 5 "Min vol_3: " 6 "Max temp_1: " 7 "Max temp_2:" 8 "Max  temp_3:" 9 "Min temp_1: " 10 "Min  temp_2: " 11 "Min  temp_3: " 12 "Max chg cur_1: " 13 "Max chg cur_2: " 14 "Max chg cur_3: " 15 "Max dchg cur_1:" 16 "Max dchg cur_2: " 17 "Max dchg cur_3: " 18 "Min iso_1: " 19 "Min iso_2:" 20 "Min iso_3:" 21 "His alarm_1: " 22 "His alarm_2: " 23 "His alarm_3: " 24 "His alarm_4: " 25 "His alarm_5: " 26 "His alarm_6: " ;
VAL_ 2416045716 M2P_DIAG_BYTE1_04 0 "Nvm data" ;
VAL_ 2416045716 M2P_DIAG_BYTE2_04 0 "Max vol_1: " 1 "Max vol_2: " 2 "Max vol_3: " 3 "Min vol_1:" 4 "Min vol_2: " 5 "Min vol_3: " 6 "Max temp_1: " 7 "Max temp_2:" 8 "Max  temp_3:" 9 "Min temp_1: " 10 "Min  temp_2: " 11 "Min  temp_3: " 12 "Max chg cur_1: " 13 "Max chg cur_2: " 14 "Max chg cur_3: " 15 "Max dchg cur_1:" 16 "Max dchg cur_2: " 17 "Max dchg cur_3: " 18 "Min iso_1: " 19 "Min iso_2:" 20 "Min iso_3:" 21 "His alarm_1: " 22 "His alarm_2: " 23 "His alarm_3: " 24 "His alarm_4: " 25 "His alarm_5: " 26 "His alarm_6: " ;
VAL_ 2416045717 M2P_DIAG_BYTE1_05 0 "Nvm data" ;
VAL_ 2416045717 M2P_DIAG_BYTE2_05 0 "Max vol_1: " 1 "Max vol_2: " 2 "Max vol_3: " 3 "Min vol_1:" 4 "Min vol_2: " 5 "Min vol_3: " 6 "Max temp_1: " 7 "Max temp_2:" 8 "Max  temp_3:" 9 "Min temp_1: " 10 "Min  temp_2: " 11 "Min  temp_3: " 12 "Max chg cur_1: " 13 "Max chg cur_2: " 14 "Max chg cur_3: " 15 "Max dchg cur_1:" 16 "Max dchg cur_2: " 17 "Max dchg cur_3: " 18 "Min iso_1: " 19 "Min iso_2:" 20 "Min iso_3:" 21 "His alarm_1: " 22 "His alarm_2: " 23 "His alarm_3: " 24 "His alarm_4: " 25 "His alarm_5: " 26 "His alarm_6: " ;
VAL_ 2416045718 M2P_DIAG_BYTE1_06 0 "Nvm data" ;
VAL_ 2416045718 M2P_DIAG_BYTE2_06 0 "Max vol_1: " 1 "Max vol_2: " 2 "Max vol_3: " 3 "Min vol_1:" 4 "Min vol_2: " 5 "Min vol_3: " 6 "Max temp_1: " 7 "Max temp_2:" 8 "Max  temp_3:" 9 "Min temp_1: " 10 "Min  temp_2: " 11 "Min  temp_3: " 12 "Max chg cur_1: " 13 "Max chg cur_2: " 14 "Max chg cur_3: " 15 "Max dchg cur_1:" 16 "Max dchg cur_2: " 17 "Max dchg cur_3: " 18 "Min iso_1: " 19 "Min iso_2:" 20 "Min iso_3:" 21 "His alarm_1: " 22 "His alarm_2: " 23 "His alarm_3: " 24 "His alarm_4: " 25 "His alarm_5: " 26 "His alarm_6: " ;
VAL_ 2416045719 M2P_DIAG_BYTE1_07 0 "Nvm data" ;
VAL_ 2416045719 M2P_DIAG_BYTE2_07 0 "Max vol_1: " 1 "Max vol_2: " 2 "Max vol_3: " 3 "Min vol_1:" 4 "Min vol_2: " 5 "Min vol_3: " 6 "Max temp_1: " 7 "Max temp_2:" 8 "Max  temp_3:" 9 "Min temp_1: " 10 "Min  temp_2: " 11 "Min  temp_3: " 12 "Max chg cur_1: " 13 "Max chg cur_2: " 14 "Max chg cur_3: " 15 "Max dchg cur_1:" 16 "Max dchg cur_2: " 17 "Max dchg cur_3: " 18 "Min iso_1: " 19 "Min iso_2:" 20 "Min iso_3:" 21 "His alarm_1: " 22 "His alarm_2: " 23 "His alarm_3: " 24 "His alarm_4: " 25 "His alarm_5: " 26 "His alarm_6: " ;
VAL_ 2416045720 M2P_DIAG_BYTE1_08 0 "Nvm data" ;
VAL_ 2416045720 M2P_DIAG_BYTE2_08 0 "Max vol_1: " 1 "Max vol_2: " 2 "Max vol_3: " 3 "Min vol_1:" 4 "Min vol_2: " 5 "Min vol_3: " 6 "Max temp_1: " 7 "Max temp_2:" 8 "Max  temp_3:" 9 "Min temp_1: " 10 "Min  temp_2: " 11 "Min  temp_3: " 12 "Max chg cur_1: " 13 "Max chg cur_2: " 14 "Max chg cur_3: " 15 "Max dchg cur_1:" 16 "Max dchg cur_2: " 17 "Max dchg cur_3: " 18 "Min iso_1: " 19 "Min iso_2:" 20 "Min iso_3:" 21 "His alarm_1: " 22 "His alarm_2: " 23 "His alarm_3: " 24 "His alarm_4: " 25 "His alarm_5: " 26 "His alarm_6: " ;
VAL_ 2416045721 M2P_DIAG_BYTE1_09 0 "Nvm data" ;
VAL_ 2416045721 M2P_DIAG_BYTE2_09 0 "Max vol_1: " 1 "Max vol_2: " 2 "Max vol_3: " 3 "Min vol_1:" 4 "Min vol_2: " 5 "Min vol_3: " 6 "Max temp_1: " 7 "Max temp_2:" 8 "Max  temp_3:" 9 "Min temp_1: " 10 "Min  temp_2: " 11 "Min  temp_3: " 12 "Max chg cur_1: " 13 "Max chg cur_2: " 14 "Max chg cur_3: " 15 "Max dchg cur_1:" 16 "Max dchg cur_2: " 17 "Max dchg cur_3: " 18 "Min iso_1: " 19 "Min iso_2:" 20 "Min iso_3:" 21 "His alarm_1: " 22 "His alarm_2: " 23 "His alarm_3: " 24 "His alarm_4: " 25 "His alarm_5: " 26 "His alarm_6: " ;
VAL_ 2416045722 M2P_DIAG_BYTE1_10 0 "Nvm data" ;
VAL_ 2416045722 M2P_DIAG_BYTE2_10 0 "Max vol_1: " 1 "Max vol_2: " 2 "Max vol_3: " 3 "Min vol_1:" 4 "Min vol_2: " 5 "Min vol_3: " 6 "Max temp_1: " 7 "Max temp_2:" 8 "Max  temp_3:" 9 "Min temp_1: " 10 "Min  temp_2: " 11 "Min  temp_3: " 12 "Max chg cur_1: " 13 "Max chg cur_2: " 14 "Max chg cur_3: " 15 "Max dchg cur_1:" 16 "Max dchg cur_2: " 17 "Max dchg cur_3: " 18 "Min iso_1: " 19 "Min iso_2:" 20 "Min iso_3:" 21 "His alarm_1: " 22 "His alarm_2: " 23 "His alarm_3: " 24 "His alarm_4: " 25 "His alarm_5: " 26 "His alarm_6: " ;
VAL_ 2416045723 M2P_DIAG_BYTE1_11 0 "Nvm data" ;
VAL_ 2416045723 M2P_DIAG_BYTE2_11 0 "Max vol_1: " 1 "Max vol_2: " 2 "Max vol_3: " 3 "Min vol_1:" 4 "Min vol_2: " 5 "Min vol_3: " 6 "Max temp_1: " 7 "Max temp_2:" 8 "Max  temp_3:" 9 "Min temp_1: " 10 "Min  temp_2: " 11 "Min  temp_3: " 12 "Max chg cur_1: " 13 "Max chg cur_2: " 14 "Max chg cur_3: " 15 "Max dchg cur_1:" 16 "Max dchg cur_2: " 17 "Max dchg cur_3: " 18 "Min iso_1: " 19 "Min iso_2:" 20 "Min iso_3:" 21 "His alarm_1: " 22 "His alarm_2: " 23 "His alarm_3: " 24 "His alarm_4: " 25 "His alarm_5: " 26 "His alarm_6: " ;
VAL_ 2416045724 M2P_DIAG_BYTE1_12 0 "Nvm data" ;
VAL_ 2416045724 M2P_DIAG_BYTE2_12 0 "Max vol_1: " 1 "Max vol_2: " 2 "Max vol_3: " 3 "Min vol_1:" 4 "Min vol_2: " 5 "Min vol_3: " 6 "Max temp_1: " 7 "Max temp_2:" 8 "Max  temp_3:" 9 "Min temp_1: " 10 "Min  temp_2: " 11 "Min  temp_3: " 12 "Max chg cur_1: " 13 "Max chg cur_2: " 14 "Max chg cur_3: " 15 "Max dchg cur_1:" 16 "Max dchg cur_2: " 17 "Max dchg cur_3: " 18 "Min iso_1: " 19 "Min iso_2:" 20 "Min iso_3:" 21 "His alarm_1: " 22 "His alarm_2: " 23 "His alarm_3: " 24 "His alarm_4: " 25 "His alarm_5: " 26 "His alarm_6: " ;
VAL_ 2416045725 M2P_DIAG_BYTE1_13 0 "Nvm data" ;
VAL_ 2416045725 M2P_DIAG_BYTE2_13 0 "Max vol_1: " 1 "Max vol_2: " 2 "Max vol_3: " 3 "Min vol_1:" 4 "Min vol_2: " 5 "Min vol_3: " 6 "Max temp_1: " 7 "Max temp_2:" 8 "Max  temp_3:" 9 "Min temp_1: " 10 "Min  temp_2: " 11 "Min  temp_3: " 12 "Max chg cur_1: " 13 "Max chg cur_2: " 14 "Max chg cur_3: " 15 "Max dchg cur_1:" 16 "Max dchg cur_2: " 17 "Max dchg cur_3: " 18 "Min iso_1: " 19 "Min iso_2:" 20 "Min iso_3:" 21 "His alarm_1: " 22 "His alarm_2: " 23 "His alarm_3: " 24 "His alarm_4: " 25 "His alarm_5: " 26 "His alarm_6: " ;
VAL_ 2416045726 M2P_DIAG_BYTE1_14 0 "Nvm data" ;
VAL_ 2416045726 M2P_DIAG_BYTE2_14 0 "Max vol_1: " 1 "Max vol_2: " 2 "Max vol_3: " 3 "Min vol_1:" 4 "Min vol_2: " 5 "Min vol_3: " 6 "Max temp_1: " 7 "Max temp_2:" 8 "Max  temp_3:" 9 "Min temp_1: " 10 "Min  temp_2: " 11 "Min  temp_3: " 12 "Max chg cur_1: " 13 "Max chg cur_2: " 14 "Max chg cur_3: " 15 "Max dchg cur_1:" 16 "Max dchg cur_2: " 17 "Max dchg cur_3: " 18 "Min iso_1: " 19 "Min iso_2:" 20 "Min iso_3:" 21 "His alarm_1: " 22 "His alarm_2: " 23 "His alarm_3: " 24 "His alarm_4: " 25 "His alarm_5: " 26 "His alarm_6: " ;
VAL_ 2416045727 M2P_DIAG_BYTE1_15 0 "Nvm data" ;
VAL_ 2416045727 M2P_DIAG_BYTE2_15 0 "Max vol_1: " 1 "Max vol_2: " 2 "Max vol_3: " 3 "Min vol_1:" 4 "Min vol_2: " 5 "Min vol_3: " 6 "Max temp_1: " 7 "Max temp_2:" 8 "Max  temp_3:" 9 "Min temp_1: " 10 "Min  temp_2: " 11 "Min  temp_3: " 12 "Max chg cur_1: " 13 "Max chg cur_2: " 14 "Max chg cur_3: " 15 "Max dchg cur_1:" 16 "Max dchg cur_2: " 17 "Max dchg cur_3: " 18 "Min iso_1: " 19 "Min iso_2:" 20 "Min iso_3:" 21 "His alarm_1: " 22 "His alarm_2: " 23 "His alarm_3: " 24 "His alarm_4: " 25 "His alarm_5: " 26 "His alarm_6: " ;
VAL_ 2416045728 M2P_DIAG_BYTE1_16 0 "Nvm data" ;
VAL_ 2416045728 M2P_DIAG_BYTE2_16 0 "Max vol_1: " 1 "Max vol_2: " 2 "Max vol_3: " 3 "Min vol_1:" 4 "Min vol_2: " 5 "Min vol_3: " 6 "Max temp_1: " 7 "Max temp_2:" 8 "Max  temp_3:" 9 "Min temp_1: " 10 "Min  temp_2: " 11 "Min  temp_3: " 12 "Max chg cur_1: " 13 "Max chg cur_2: " 14 "Max chg cur_3: " 15 "Max dchg cur_1:" 16 "Max dchg cur_2: " 17 "Max dchg cur_3: " 18 "Min iso_1: " 19 "Min iso_2:" 20 "Min iso_3:" 21 "His alarm_1: " 22 "His alarm_2: " 23 "His alarm_3: " 24 "His alarm_4: " 25 "His alarm_5: " 26 "His alarm_6: " ;
VAL_ 2416045729 M2P_DIAG_BYTE1_17 0 "Nvm data" ;
VAL_ 2416045729 M2P_DIAG_BYTE2_17 0 "Max vol_1: " 1 "Max vol_2: " 2 "Max vol_3: " 3 "Min vol_1:" 4 "Min vol_2: " 5 "Min vol_3: " 6 "Max temp_1: " 7 "Max temp_2:" 8 "Max  temp_3:" 9 "Min temp_1: " 10 "Min  temp_2: " 11 "Min  temp_3: " 12 "Max chg cur_1: " 13 "Max chg cur_2: " 14 "Max chg cur_3: " 15 "Max dchg cur_1:" 16 "Max dchg cur_2: " 17 "Max dchg cur_3: " 18 "Min iso_1: " 19 "Min iso_2:" 20 "Min iso_3:" 21 "His alarm_1: " 22 "His alarm_2: " 23 "His alarm_3: " 24 "His alarm_4: " 25 "His alarm_5: " 26 "His alarm_6: " ;
VAL_ 2416045730 M2P_DIAG_BYTE1_18 0 "Nvm data" ;
VAL_ 2416045730 M2P_DIAG_BYTE2_18 0 "Max vol_1: " 1 "Max vol_2: " 2 "Max vol_3: " 3 "Min vol_1:" 4 "Min vol_2: " 5 "Min vol_3: " 6 "Max temp_1: " 7 "Max temp_2:" 8 "Max  temp_3:" 9 "Min temp_1: " 10 "Min  temp_2: " 11 "Min  temp_3: " 12 "Max chg cur_1: " 13 "Max chg cur_2: " 14 "Max chg cur_3: " 15 "Max dchg cur_1:" 16 "Max dchg cur_2: " 17 "Max dchg cur_3: " 18 "Min iso_1: " 19 "Min iso_2:" 20 "Min iso_3:" 21 "His alarm_1: " 22 "His alarm_2: " 23 "His alarm_3: " 24 "His alarm_4: " 25 "His alarm_5: " 26 "His alarm_6: " ;
VAL_ 2416045731 M2P_DIAG_BYTE1_19 0 "Nvm data" ;
VAL_ 2416045731 M2P_DIAG_BYTE2_19 0 "Max vol_1: " 1 "Max vol_2: " 2 "Max vol_3: " 3 "Min vol_1:" 4 "Min vol_2: " 5 "Min vol_3: " 6 "Max temp_1: " 7 "Max temp_2:" 8 "Max  temp_3:" 9 "Min temp_1: " 10 "Min  temp_2: " 11 "Min  temp_3: " 12 "Max chg cur_1: " 13 "Max chg cur_2: " 14 "Max chg cur_3: " 15 "Max dchg cur_1:" 16 "Max dchg cur_2: " 17 "Max dchg cur_3: " 18 "Min iso_1: " 19 "Min iso_2:" 20 "Min iso_3:" 21 "His alarm_1: " 22 "His alarm_2: " 23 "His alarm_3: " 24 "His alarm_4: " 25 "His alarm_5: " 26 "His alarm_6: " ;
VAL_ 2416045732 M2P_DIAG_BYTE1_20 0 "Nvm data" ;
VAL_ 2416045732 M2P_DIAG_BYTE2_20 0 "Max vol_1: " 1 "Max vol_2: " 2 "Max vol_3: " 3 "Min vol_1:" 4 "Min vol_2: " 5 "Min vol_3: " 6 "Max temp_1: " 7 "Max temp_2:" 8 "Max  temp_3:" 9 "Min temp_1: " 10 "Min  temp_2: " 11 "Min  temp_3: " 12 "Max chg cur_1: " 13 "Max chg cur_2: " 14 "Max chg cur_3: " 15 "Max dchg cur_1:" 16 "Max dchg cur_2: " 17 "Max dchg cur_3: " 18 "Min iso_1: " 19 "Min iso_2:" 20 "Min iso_3:" 21 "His alarm_1: " 22 "His alarm_2: " 23 "His alarm_3: " 24 "His alarm_4: " 25 "His alarm_5: " 26 "His alarm_6: " ;
VAL_ 2416045733 M2P_DIAG_BYTE1_21 0 "Nvm data" ;
VAL_ 2416045733 M2P_DIAG_BYTE2_21 0 "Max vol_1: " 1 "Max vol_2: " 2 "Max vol_3: " 3 "Min vol_1:" 4 "Min vol_2: " 5 "Min vol_3: " 6 "Max temp_1: " 7 "Max temp_2:" 8 "Max  temp_3:" 9 "Min temp_1: " 10 "Min  temp_2: " 11 "Min  temp_3: " 12 "Max chg cur_1: " 13 "Max chg cur_2: " 14 "Max chg cur_3: " 15 "Max dchg cur_1:" 16 "Max dchg cur_2: " 17 "Max dchg cur_3: " 18 "Min iso_1: " 19 "Min iso_2:" 20 "Min iso_3:" 21 "His alarm_1: " 22 "His alarm_2: " 23 "His alarm_3: " 24 "His alarm_4: " 25 "His alarm_5: " 26 "His alarm_6: " ;
VAL_ 2416045734 M2P_DIAG_BYTE1_22 0 "Nvm data" ;
VAL_ 2416045734 M2P_DIAG_BYTE2_22 0 "Max vol_1: " 1 "Max vol_2: " 2 "Max vol_3: " 3 "Min vol_1:" 4 "Min vol_2: " 5 "Min vol_3: " 6 "Max temp_1: " 7 "Max temp_2:" 8 "Max  temp_3:" 9 "Min temp_1: " 10 "Min  temp_2: " 11 "Min  temp_3: " 12 "Max chg cur_1: " 13 "Max chg cur_2: " 14 "Max chg cur_3: " 15 "Max dchg cur_1:" 16 "Max dchg cur_2: " 17 "Max dchg cur_3: " 18 "Min iso_1: " 19 "Min iso_2:" 20 "Min iso_3:" 21 "His alarm_1: " 22 "His alarm_2: " 23 "His alarm_3: " 24 "His alarm_4: " 25 "His alarm_5: " 26 "His alarm_6: " ;
VAL_ 2416045735 M2P_DIAG_BYTE1_23 0 "Nvm data" ;
VAL_ 2416045735 M2P_DIAG_BYTE2_23 0 "Max vol_1: " 1 "Max vol_2: " 2 "Max vol_3: " 3 "Min vol_1:" 4 "Min vol_2: " 5 "Min vol_3: " 6 "Max temp_1: " 7 "Max temp_2:" 8 "Max  temp_3:" 9 "Min temp_1: " 10 "Min  temp_2: " 11 "Min  temp_3: " 12 "Max chg cur_1: " 13 "Max chg cur_2: " 14 "Max chg cur_3: " 15 "Max dchg cur_1:" 16 "Max dchg cur_2: " 17 "Max dchg cur_3: " 18 "Min iso_1: " 19 "Min iso_2:" 20 "Min iso_3:" 21 "His alarm_1: " 22 "His alarm_2: " 23 "His alarm_3: " 24 "His alarm_4: " 25 "His alarm_5: " 26 "His alarm_6: " ;
VAL_ 2416045736 M2P_DIAG_BYTE1_24 0 "Nvm data" ;
VAL_ 2416045736 M2P_DIAG_BYTE2_24 0 "Max vol_1: " 1 "Max vol_2: " 2 "Max vol_3: " 3 "Min vol_1:" 4 "Min vol_2: " 5 "Min vol_3: " 6 "Max temp_1: " 7 "Max temp_2:" 8 "Max  temp_3:" 9 "Min temp_1: " 10 "Min  temp_2: " 11 "Min  temp_3: " 12 "Max chg cur_1: " 13 "Max chg cur_2: " 14 "Max chg cur_3: " 15 "Max dchg cur_1:" 16 "Max dchg cur_2: " 17 "Max dchg cur_3: " 18 "Min iso_1: " 19 "Min iso_2:" 20 "Min iso_3:" 21 "His alarm_1: " 22 "His alarm_2: " 23 "His alarm_3: " 24 "His alarm_4: " 25 "His alarm_5: " 26 "His alarm_6: " ;
VAL_ 2416045737 M2P_DIAG_BYTE1_25 0 "Nvm data" ;
VAL_ 2416045737 M2P_DIAG_BYTE2_25 0 "Max vol_1: " 1 "Max vol_2: " 2 "Max vol_3: " 3 "Min vol_1:" 4 "Min vol_2: " 5 "Min vol_3: " 6 "Max temp_1: " 7 "Max temp_2:" 8 "Max  temp_3:" 9 "Min temp_1: " 10 "Min  temp_2: " 11 "Min  temp_3: " 12 "Max chg cur_1: " 13 "Max chg cur_2: " 14 "Max chg cur_3: " 15 "Max dchg cur_1:" 16 "Max dchg cur_2: " 17 "Max dchg cur_3: " 18 "Min iso_1: " 19 "Min iso_2:" 20 "Min iso_3:" 21 "His alarm_1: " 22 "His alarm_2: " 23 "His alarm_3: " 24 "His alarm_4: " 25 "His alarm_5: " 26 "His alarm_6: " ;
VAL_ 2416045738 M2P_DIAG_BYTE1_26 0 "Nvm data" ;
VAL_ 2416045738 M2P_DIAG_BYTE2_26 0 "Max vol_1: " 1 "Max vol_2: " 2 "Max vol_3: " 3 "Min vol_1:" 4 "Min vol_2: " 5 "Min vol_3: " 6 "Max temp_1: " 7 "Max temp_2:" 8 "Max  temp_3:" 9 "Min temp_1: " 10 "Min  temp_2: " 11 "Min  temp_3: " 12 "Max chg cur_1: " 13 "Max chg cur_2: " 14 "Max chg cur_3: " 15 "Max dchg cur_1:" 16 "Max dchg cur_2: " 17 "Max dchg cur_3: " 18 "Min iso_1: " 19 "Min iso_2:" 20 "Min iso_3:" 21 "His alarm_1: " 22 "His alarm_2: " 23 "His alarm_3: " 24 "His alarm_4: " 25 "His alarm_5: " 26 "His alarm_6: " ;
VAL_ 2416045739 M2P_DIAG_BYTE1_27 0 "Nvm data" ;
VAL_ 2416045739 M2P_DIAG_BYTE2_27 0 "Max vol_1: " 1 "Max vol_2: " 2 "Max vol_3: " 3 "Min vol_1:" 4 "Min vol_2: " 5 "Min vol_3: " 6 "Max temp_1: " 7 "Max temp_2:" 8 "Max  temp_3:" 9 "Min temp_1: " 10 "Min  temp_2: " 11 "Min  temp_3: " 12 "Max chg cur_1: " 13 "Max chg cur_2: " 14 "Max chg cur_3: " 15 "Max dchg cur_1:" 16 "Max dchg cur_2: " 17 "Max dchg cur_3: " 18 "Min iso_1: " 19 "Min iso_2:" 20 "Min iso_3:" 21 "His alarm_1: " 22 "His alarm_2: " 23 "His alarm_3: " 24 "His alarm_4: " 25 "His alarm_5: " 26 "His alarm_6: " ;
VAL_ 2416045740 M2P_DIAG_BYTE1_28 0 "Nvm data" ;
VAL_ 2416045740 M2P_DIAG_BYTE2_28 0 "Max vol_1: " 1 "Max vol_2: " 2 "Max vol_3: " 3 "Min vol_1:" 4 "Min vol_2: " 5 "Min vol_3: " 6 "Max temp_1: " 7 "Max temp_2:" 8 "Max  temp_3:" 9 "Min temp_1: " 10 "Min  temp_2: " 11 "Min  temp_3: " 12 "Max chg cur_1: " 13 "Max chg cur_2: " 14 "Max chg cur_3: " 15 "Max dchg cur_1:" 16 "Max dchg cur_2: " 17 "Max dchg cur_3: " 18 "Min iso_1: " 19 "Min iso_2:" 20 "Min iso_3:" 21 "His alarm_1: " 22 "His alarm_2: " 23 "His alarm_3: " 24 "His alarm_4: " 25 "His alarm_5: " 26 "His alarm_6: " ;
VAL_ 2416045741 M2P_DIAG_BYTE1_29 0 "Nvm data" ;
VAL_ 2416045741 M2P_DIAG_BYTE2_29 0 "Max vol_1: " 1 "Max vol_2: " 2 "Max vol_3: " 3 "Min vol_1:" 4 "Min vol_2: " 5 "Min vol_3: " 6 "Max temp_1: " 7 "Max temp_2:" 8 "Max  temp_3:" 9 "Min temp_1: " 10 "Min  temp_2: " 11 "Min  temp_3: " 12 "Max chg cur_1: " 13 "Max chg cur_2: " 14 "Max chg cur_3: " 15 "Max dchg cur_1:" 16 "Max dchg cur_2: " 17 "Max dchg cur_3: " 18 "Min iso_1: " 19 "Min iso_2:" 20 "Min iso_3:" 21 "His alarm_1: " 22 "His alarm_2: " 23 "His alarm_3: " 24 "His alarm_4: " 25 "His alarm_5: " 26 "His alarm_6: " ;
VAL_ 2416045742 M2P_DIAG_BYTE1_30 0 "Nvm data" ;
VAL_ 2416045742 M2P_DIAG_BYTE2_30 0 "Max vol_1: " 1 "Max vol_2: " 2 "Max vol_3: " 3 "Min vol_1:" 4 "Min vol_2: " 5 "Min vol_3: " 6 "Max temp_1: " 7 "Max temp_2:" 8 "Max  temp_3:" 9 "Min temp_1: " 10 "Min  temp_2: " 11 "Min  temp_3: " 12 "Max chg cur_1: " 13 "Max chg cur_2: " 14 "Max chg cur_3: " 15 "Max dchg cur_1:" 16 "Max dchg cur_2: " 17 "Max dchg cur_3: " 18 "Min iso_1: " 19 "Min iso_2:" 20 "Min iso_3:" 21 "His alarm_1: " 22 "His alarm_2: " 23 "His alarm_3: " 24 "His alarm_4: " 25 "His alarm_5: " 26 "His alarm_6: " ;
VAL_ 2416045743 M2P_DIAG_BYTE1_31 0 "Nvm data" ;
VAL_ 2416045743 M2P_DIAG_BYTE2_31 0 "Max vol_1: " 1 "Max vol_2: " 2 "Max vol_3: " 3 "Min vol_1:" 4 "Min vol_2: " 5 "Min vol_3: " 6 "Max temp_1: " 7 "Max temp_2:" 8 "Max  temp_3:" 9 "Min temp_1: " 10 "Min  temp_2: " 11 "Min  temp_3: " 12 "Max chg cur_1: " 13 "Max chg cur_2: " 14 "Max chg cur_3: " 15 "Max dchg cur_1:" 16 "Max dchg cur_2: " 17 "Max dchg cur_3: " 18 "Min iso_1: " 19 "Min iso_2:" 20 "Min iso_3:" 21 "His alarm_1: " 22 "His alarm_2: " 23 "His alarm_3: " 24 "His alarm_4: " 25 "His alarm_5: " 26 "His alarm_6: " ;
VERSION ""

NS_ :

BS_:

BU_: MBMU PC SBMU IMM ETH DCDC LEMS

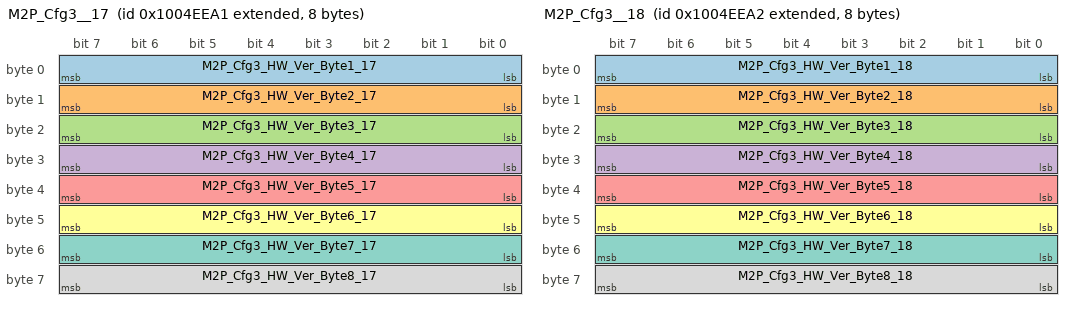
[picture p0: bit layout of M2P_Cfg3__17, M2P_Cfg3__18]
BO_ 2416242337 M2P_Cfg3__17: 8 MBMU
 SG_ M2P_Cfg3_HW_Ver_Byte1_17 : 0|8@1+ (1,0) [0|255] ""  PC
 SG_ M2P_Cfg3_HW_Ver_Byte2_17 : 8|8@1+ (1,0) [0|255] ""  PC
 SG_ M2P_Cfg3_HW_Ver_Byte3_17 : 16|8@1+ (1,0) [0|255] ""  PC
 SG_ M2P_Cfg3_HW_Ver_Byte4_17 : 24|8@1+ (1,0) [0|255] ""  PC
 SG_ M2P_Cfg3_HW_Ver_Byte5_17 : 32|8@1+ (1,0) [0|255] ""  PC
 SG_ M2P_Cfg3_HW_Ver_Byte6_17 : 40|8@1+ (1,0) [0|255] ""  PC
 SG_ M2P_Cfg3_HW_Ver_Byte7_17 : 48|8@1+ (1,0) [0|255] ""  PC
 SG_ M2P_Cfg3_HW_Ver_Byte8_17 : 56|8@1+ (1,0) [0|255] ""  PC

BO_ 2416242338 M2P_Cfg3__18: 8 MBMU
 SG_ M2P_Cfg3_HW_Ver_Byte1_18 : 0|8@1+ (1,0) [0|255] ""  PC
 SG_ M2P_Cfg3_HW_Ver_Byte2_18 : 8|8@1+ (1,0) [0|255] ""  PC
 SG_ M2P_Cfg3_HW_Ver_Byte3_18 : 16|8@1+ (1,0) [0|255] ""  PC
 SG_ M2P_Cfg3_HW_Ver_Byte4_18 : 24|8@1+ (1,0) [0|255] ""  PC
 SG_ M2P_Cfg3_HW_Ver_Byte5_18 : 32|8@1+ (1,0) [0|255] ""  PC
 SG_ M2P_Cfg3_HW_Ver_Byte6_18 : 40|8@1+ (1,0) [0|255] ""  PC
 SG_ M2P_Cfg3_HW_Ver_Byte7_18 : 48|8@1+ (1,0) [0|255] ""  PC
 SG_ M2P_Cfg3_HW_Ver_Byte8_18 : 56|8@1+ (1,0) [0|255] ""  PC

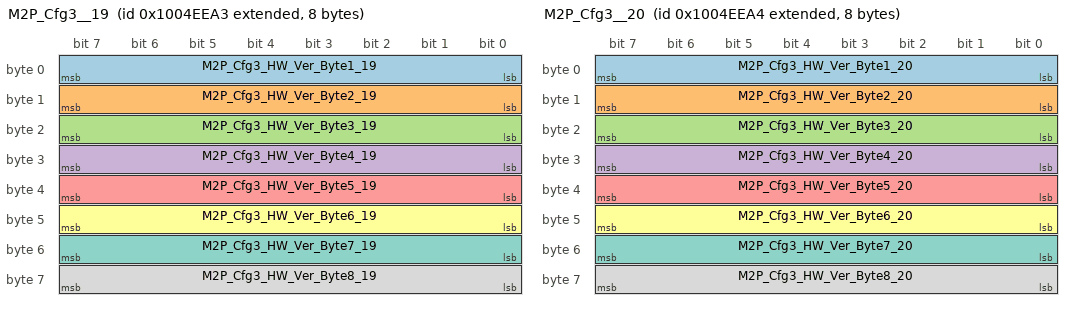
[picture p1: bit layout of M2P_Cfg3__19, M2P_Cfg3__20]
BO_ 2416242339 M2P_Cfg3__19: 8 MBMU
 SG_ M2P_Cfg3_HW_Ver_Byte1_19 : 0|8@1+ (1,0) [0|255] ""  PC
 SG_ M2P_Cfg3_HW_Ver_Byte2_19 : 8|8@1+ (1,0) [0|255] ""  PC
 SG_ M2P_Cfg3_HW_Ver_Byte3_19 : 16|8@1+ (1,0) [0|255] ""  PC
 SG_ M2P_Cfg3_HW_Ver_Byte4_19 : 24|8@1+ (1,0) [0|255] ""  PC
 SG_ M2P_Cfg3_HW_Ver_Byte5_19 : 32|8@1+ (1,0) [0|255] ""  PC
 SG_ M2P_Cfg3_HW_Ver_Byte6_19 : 40|8@1+ (1,0) [0|255] ""  PC
 SG_ M2P_Cfg3_HW_Ver_Byte7_19 : 48|8@1+ (1,0) [0|255] ""  PC
 SG_ M2P_Cfg3_HW_Ver_Byte8_19 : 56|8@1+ (1,0) [0|255] ""  PC

BO_ 2416242340 M2P_Cfg3__20: 8 MBMU
 SG_ M2P_Cfg3_HW_Ver_Byte1_20 : 0|8@1+ (1,0) [0|255] ""  PC
 SG_ M2P_Cfg3_HW_Ver_Byte2_20 : 8|8@1+ (1,0) [0|255] ""  PC
 SG_ M2P_Cfg3_HW_Ver_Byte3_20 : 16|8@1+ (1,0) [0|255] ""  PC
 SG_ M2P_Cfg3_HW_Ver_Byte4_20 : 24|8@1+ (1,0) [0|255] ""  PC
 SG_ M2P_Cfg3_HW_Ver_Byte5_20 : 32|8@1+ (1,0) [0|255] ""  PC
 SG_ M2P_Cfg3_HW_Ver_Byte6_20 : 40|8@1+ (1,0) [0|255] ""  PC
 SG_ M2P_Cfg3_HW_Ver_Byte7_20 : 48|8@1+ (1,0) [0|255] ""  PC
 SG_ M2P_Cfg3_HW_Ver_Byte8_20 : 56|8@1+ (1,0) [0|255] ""  PC

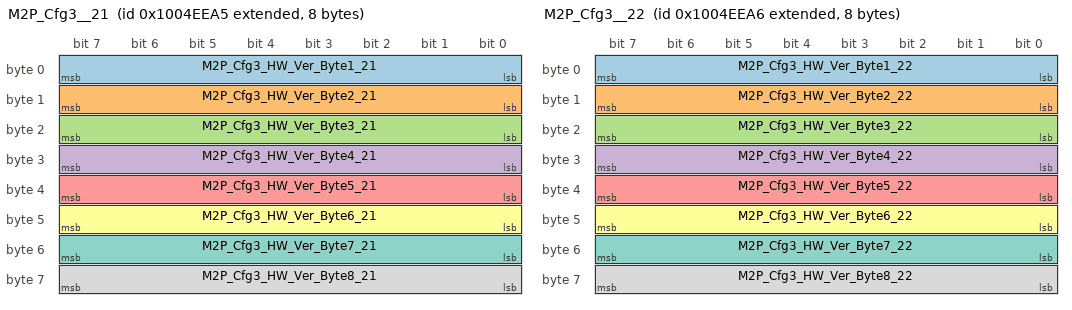
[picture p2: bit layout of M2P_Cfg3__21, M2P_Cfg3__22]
BO_ 2416242341 M2P_Cfg3__21: 8 MBMU
 SG_ M2P_Cfg3_HW_Ver_Byte1_21 : 0|8@1+ (1,0) [0|255] ""  PC
 SG_ M2P_Cfg3_HW_Ver_Byte2_21 : 8|8@1+ (1,0) [0|255] ""  PC
 SG_ M2P_Cfg3_HW_Ver_Byte3_21 : 16|8@1+ (1,0) [0|255] ""  PC
 SG_ M2P_Cfg3_HW_Ver_Byte4_21 : 24|8@1+ (1,0) [0|255] ""  PC
 SG_ M2P_Cfg3_HW_Ver_Byte5_21 : 32|8@1+ (1,0) [0|255] ""  PC
 SG_ M2P_Cfg3_HW_Ver_Byte6_21 : 40|8@1+ (1,0) [0|255] ""  PC
 SG_ M2P_Cfg3_HW_Ver_Byte7_21 : 48|8@1+ (1,0) [0|255] ""  PC
 SG_ M2P_Cfg3_HW_Ver_Byte8_21 : 56|8@1+ (1,0) [0|255] ""  PC

BO_ 2416242342 M2P_Cfg3__22: 8 MBMU
 SG_ M2P_Cfg3_HW_Ver_Byte1_22 : 0|8@1+ (1,0) [0|255] ""  PC
 SG_ M2P_Cfg3_HW_Ver_Byte2_22 : 8|8@1+ (1,0) [0|255] ""  PC
 SG_ M2P_Cfg3_HW_Ver_Byte3_22 : 16|8@1+ (1,0) [0|255] ""  PC
 SG_ M2P_Cfg3_HW_Ver_Byte4_22 : 24|8@1+ (1,0) [0|255] ""  PC
 SG_ M2P_Cfg3_HW_Ver_Byte5_22 : 32|8@1+ (1,0) [0|255] ""  PC
 SG_ M2P_Cfg3_HW_Ver_Byte6_22 : 40|8@1+ (1,0) [0|255] ""  PC
 SG_ M2P_Cfg3_HW_Ver_Byte7_22 : 48|8@1+ (1,0) [0|255] ""  PC
 SG_ M2P_Cfg3_HW_Ver_Byte8_22 : 56|8@1+ (1,0) [0|255] ""  PC

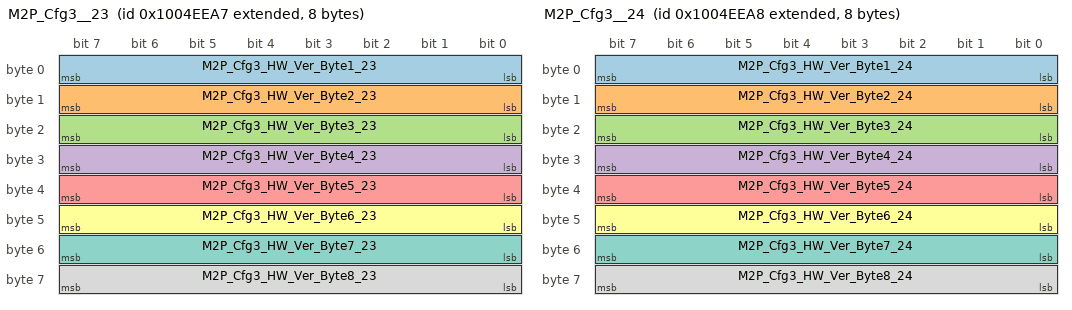
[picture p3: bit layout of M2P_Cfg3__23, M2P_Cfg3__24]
BO_ 2416242343 M2P_Cfg3__23: 8 MBMU
 SG_ M2P_Cfg3_HW_Ver_Byte1_23 : 0|8@1+ (1,0) [0|255] ""  PC
 SG_ M2P_Cfg3_HW_Ver_Byte2_23 : 8|8@1+ (1,0) [0|255] ""  PC
 SG_ M2P_Cfg3_HW_Ver_Byte3_23 : 16|8@1+ (1,0) [0|255] ""  PC
 SG_ M2P_Cfg3_HW_Ver_Byte4_23 : 24|8@1+ (1,0) [0|255] ""  PC
 SG_ M2P_Cfg3_HW_Ver_Byte5_23 : 32|8@1+ (1,0) [0|255] ""  PC
 SG_ M2P_Cfg3_HW_Ver_Byte6_23 : 40|8@1+ (1,0) [0|255] ""  PC
 SG_ M2P_Cfg3_HW_Ver_Byte7_23 : 48|8@1+ (1,0) [0|255] ""  PC
 SG_ M2P_Cfg3_HW_Ver_Byte8_23 : 56|8@1+ (1,0) [0|255] ""  PC

BO_ 2416242344 M2P_Cfg3__24: 8 MBMU
 SG_ M2P_Cfg3_HW_Ver_Byte1_24 : 0|8@1+ (1,0) [0|255] ""  PC
 SG_ M2P_Cfg3_HW_Ver_Byte2_24 : 8|8@1+ (1,0) [0|255] ""  PC
 SG_ M2P_Cfg3_HW_Ver_Byte3_24 : 16|8@1+ (1,0) [0|255] ""  PC
 SG_ M2P_Cfg3_HW_Ver_Byte4_24 : 24|8@1+ (1,0) [0|255] ""  PC
 SG_ M2P_Cfg3_HW_Ver_Byte5_24 : 32|8@1+ (1,0) [0|255] ""  PC
 SG_ M2P_Cfg3_HW_Ver_Byte6_24 : 40|8@1+ (1,0) [0|255] ""  PC
 SG_ M2P_Cfg3_HW_Ver_Byte7_24 : 48|8@1+ (1,0) [0|255] ""  PC
 SG_ M2P_Cfg3_HW_Ver_Byte8_24 : 56|8@1+ (1,0) [0|255] ""  PC

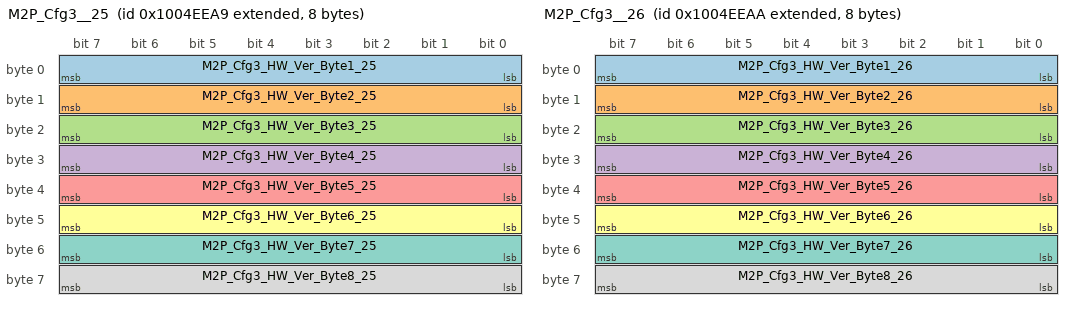
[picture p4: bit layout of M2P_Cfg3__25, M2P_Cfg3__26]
BO_ 2416242345 M2P_Cfg3__25: 8 MBMU
 SG_ M2P_Cfg3_HW_Ver_Byte1_25 : 0|8@1+ (1,0) [0|255] ""  PC
 SG_ M2P_Cfg3_HW_Ver_Byte2_25 : 8|8@1+ (1,0) [0|255] ""  PC
 SG_ M2P_Cfg3_HW_Ver_Byte3_25 : 16|8@1+ (1,0) [0|255] ""  PC
 SG_ M2P_Cfg3_HW_Ver_Byte4_25 : 24|8@1+ (1,0) [0|255] ""  PC
 SG_ M2P_Cfg3_HW_Ver_Byte5_25 : 32|8@1+ (1,0) [0|255] ""  PC
 SG_ M2P_Cfg3_HW_Ver_Byte6_25 : 40|8@1+ (1,0) [0|255] ""  PC
 SG_ M2P_Cfg3_HW_Ver_Byte7_25 : 48|8@1+ (1,0) [0|255] ""  PC
 SG_ M2P_Cfg3_HW_Ver_Byte8_25 : 56|8@1+ (1,0) [0|255] ""  PC

BO_ 2416242346 M2P_Cfg3__26: 8 MBMU
 SG_ M2P_Cfg3_HW_Ver_Byte1_26 : 0|8@1+ (1,0) [0|255] ""  PC
 SG_ M2P_Cfg3_HW_Ver_Byte2_26 : 8|8@1+ (1,0) [0|255] ""  PC
 SG_ M2P_Cfg3_HW_Ver_Byte3_26 : 16|8@1+ (1,0) [0|255] ""  PC
 SG_ M2P_Cfg3_HW_Ver_Byte4_26 : 24|8@1+ (1,0) [0|255] ""  PC
 SG_ M2P_Cfg3_HW_Ver_Byte5_26 : 32|8@1+ (1,0) [0|255] ""  PC
 SG_ M2P_Cfg3_HW_Ver_Byte6_26 : 40|8@1+ (1,0) [0|255] ""  PC
 SG_ M2P_Cfg3_HW_Ver_Byte7_26 : 48|8@1+ (1,0) [0|255] ""  PC
 SG_ M2P_Cfg3_HW_Ver_Byte8_26 : 56|8@1+ (1,0) [0|255] ""  PC

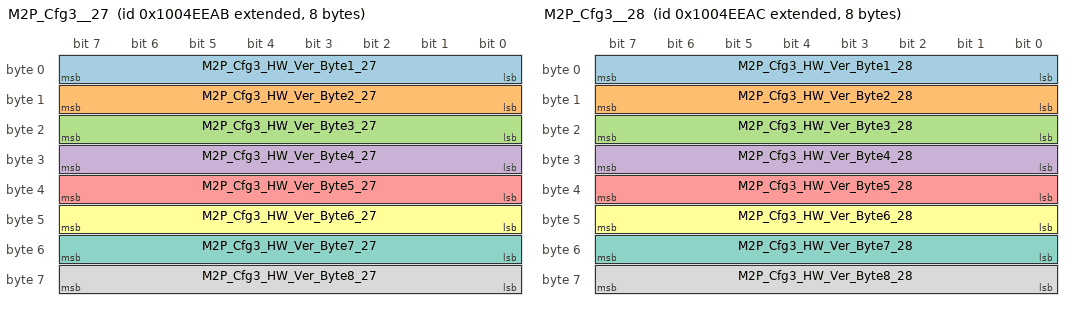
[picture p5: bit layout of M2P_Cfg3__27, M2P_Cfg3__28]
BO_ 2416242347 M2P_Cfg3__27: 8 MBMU
 SG_ M2P_Cfg3_HW_Ver_Byte1_27 : 0|8@1+ (1,0) [0|255] ""  PC
 SG_ M2P_Cfg3_HW_Ver_Byte2_27 : 8|8@1+ (1,0) [0|255] ""  PC
 SG_ M2P_Cfg3_HW_Ver_Byte3_27 : 16|8@1+ (1,0) [0|255] ""  PC
 SG_ M2P_Cfg3_HW_Ver_Byte4_27 : 24|8@1+ (1,0) [0|255] ""  PC
 SG_ M2P_Cfg3_HW_Ver_Byte5_27 : 32|8@1+ (1,0) [0|255] ""  PC
 SG_ M2P_Cfg3_HW_Ver_Byte6_27 : 40|8@1+ (1,0) [0|255] ""  PC
 SG_ M2P_Cfg3_HW_Ver_Byte7_27 : 48|8@1+ (1,0) [0|255] ""  PC
 SG_ M2P_Cfg3_HW_Ver_Byte8_27 : 56|8@1+ (1,0) [0|255] ""  PC

BO_ 2416242348 M2P_Cfg3__28: 8 MBMU
 SG_ M2P_Cfg3_HW_Ver_Byte1_28 : 0|8@1+ (1,0) [0|255] ""  PC
 SG_ M2P_Cfg3_HW_Ver_Byte2_28 : 8|8@1+ (1,0) [0|255] ""  PC
 SG_ M2P_Cfg3_HW_Ver_Byte3_28 : 16|8@1+ (1,0) [0|255] ""  PC
 SG_ M2P_Cfg3_HW_Ver_Byte4_28 : 24|8@1+ (1,0) [0|255] ""  PC
 SG_ M2P_Cfg3_HW_Ver_Byte5_28 : 32|8@1+ (1,0) [0|255] ""  PC
 SG_ M2P_Cfg3_HW_Ver_Byte6_28 : 40|8@1+ (1,0) [0|255] ""  PC
 SG_ M2P_Cfg3_HW_Ver_Byte7_28 : 48|8@1+ (1,0) [0|255] ""  PC
 SG_ M2P_Cfg3_HW_Ver_Byte8_28 : 56|8@1+ (1,0) [0|255] ""  PC

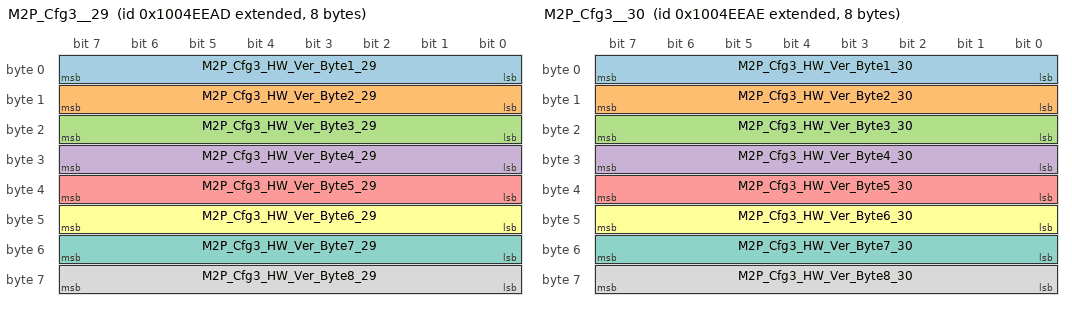
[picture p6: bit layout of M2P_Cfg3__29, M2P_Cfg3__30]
BO_ 2416242349 M2P_Cfg3__29: 8 MBMU
 SG_ M2P_Cfg3_HW_Ver_Byte1_29 : 0|8@1+ (1,0) [0|255] ""  PC
 SG_ M2P_Cfg3_HW_Ver_Byte2_29 : 8|8@1+ (1,0) [0|255] ""  PC
 SG_ M2P_Cfg3_HW_Ver_Byte3_29 : 16|8@1+ (1,0) [0|255] ""  PC
 SG_ M2P_Cfg3_HW_Ver_Byte4_29 : 24|8@1+ (1,0) [0|255] ""  PC
 SG_ M2P_Cfg3_HW_Ver_Byte5_29 : 32|8@1+ (1,0) [0|255] ""  PC
 SG_ M2P_Cfg3_HW_Ver_Byte6_29 : 40|8@1+ (1,0) [0|255] ""  PC
 SG_ M2P_Cfg3_HW_Ver_Byte7_29 : 48|8@1+ (1,0) [0|255] ""  PC
 SG_ M2P_Cfg3_HW_Ver_Byte8_29 : 56|8@1+ (1,0) [0|255] ""  PC

BO_ 2416242350 M2P_Cfg3__30: 8 MBMU
 SG_ M2P_Cfg3_HW_Ver_Byte1_30 : 0|8@1+ (1,0) [0|255] ""  PC
 SG_ M2P_Cfg3_HW_Ver_Byte2_30 : 8|8@1+ (1,0) [0|255] ""  PC
 SG_ M2P_Cfg3_HW_Ver_Byte3_30 : 16|8@1+ (1,0) [0|255] ""  PC
 SG_ M2P_Cfg3_HW_Ver_Byte4_30 : 24|8@1+ (1,0) [0|255] ""  PC
 SG_ M2P_Cfg3_HW_Ver_Byte5_30 : 32|8@1+ (1,0) [0|255] ""  PC
 SG_ M2P_Cfg3_HW_Ver_Byte6_30 : 40|8@1+ (1,0) [0|255] ""  PC
 SG_ M2P_Cfg3_HW_Ver_Byte7_30 : 48|8@1+ (1,0) [0|255] ""  PC
 SG_ M2P_Cfg3_HW_Ver_Byte8_30 : 56|8@1+ (1,0) [0|255] ""  PC

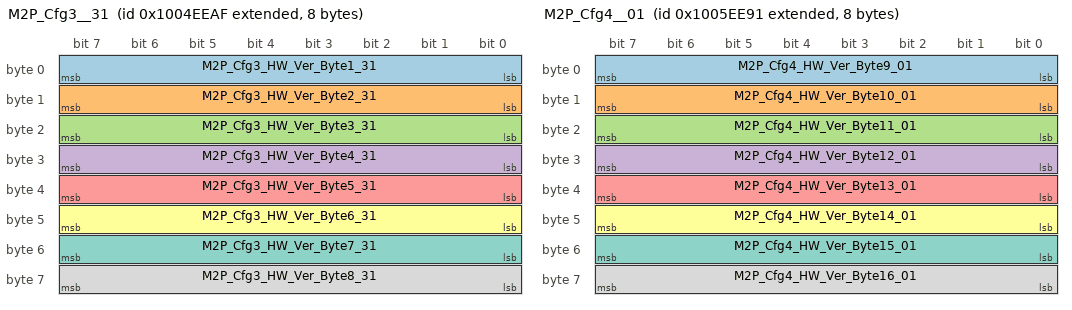
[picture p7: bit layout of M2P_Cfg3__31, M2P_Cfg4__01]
BO_ 2416242351 M2P_Cfg3__31: 8 MBMU
 SG_ M2P_Cfg3_HW_Ver_Byte1_31 : 0|8@1+ (1,0) [0|255] ""  PC
 SG_ M2P_Cfg3_HW_Ver_Byte2_31 : 8|8@1+ (1,0) [0|255] ""  PC
 SG_ M2P_Cfg3_HW_Ver_Byte3_31 : 16|8@1+ (1,0) [0|255] ""  PC
 SG_ M2P_Cfg3_HW_Ver_Byte4_31 : 24|8@1+ (1,0) [0|255] ""  PC
 SG_ M2P_Cfg3_HW_Ver_Byte5_31 : 32|8@1+ (1,0) [0|255] ""  PC
 SG_ M2P_Cfg3_HW_Ver_Byte6_31 : 40|8@1+ (1,0) [0|255] ""  PC
 SG_ M2P_Cfg3_HW_Ver_Byte7_31 : 48|8@1+ (1,0) [0|255] ""  PC
 SG_ M2P_Cfg3_HW_Ver_Byte8_31 : 56|8@1+ (1,0) [0|255] ""  PC

BO_ 2416307857 M2P_Cfg4__01: 8 MBMU
 SG_ M2P_Cfg4_HW_Ver_Byte9_01 : 0|8@1+ (1,0) [0|255] ""  PC
 SG_ M2P_Cfg4_HW_Ver_Byte10_01 : 8|8@1+ (1,0) [0|255] ""  PC
 SG_ M2P_Cfg4_HW_Ver_Byte11_01 : 16|8@1+ (1,0) [0|255] ""  PC
 SG_ M2P_Cfg4_HW_Ver_Byte12_01 : 24|8@1+ (1,0) [0|255] ""  PC
 SG_ M2P_Cfg4_HW_Ver_Byte13_01 : 32|8@1+ (1,0) [0|255] ""  PC
 SG_ M2P_Cfg4_HW_Ver_Byte14_01 : 40|8@1+ (1,0) [0|255] ""  PC
 SG_ M2P_Cfg4_HW_Ver_Byte15_01 : 48|8@1+ (1,0) [0|255] ""  PC
 SG_ M2P_Cfg4_HW_Ver_Byte16_01 : 56|8@1+ (1,0) [0|255] ""  PC

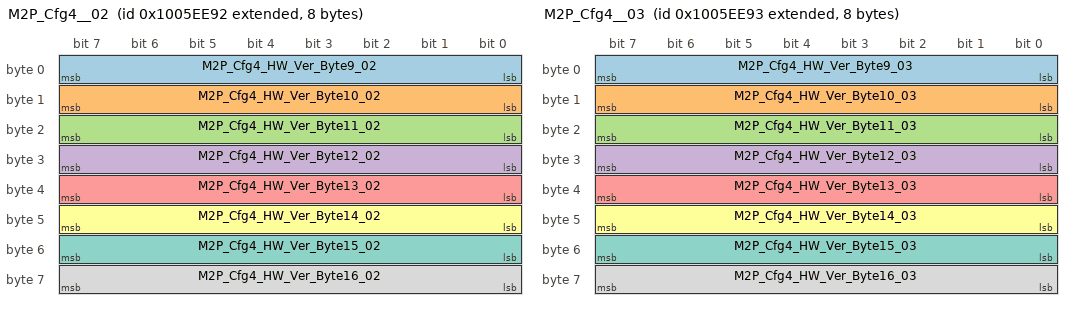
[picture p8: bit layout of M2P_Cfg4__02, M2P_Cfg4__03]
BO_ 2416307858 M2P_Cfg4__02: 8 MBMU
 SG_ M2P_Cfg4_HW_Ver_Byte9_02 : 0|8@1+ (1,0) [0|255] ""  PC
 SG_ M2P_Cfg4_HW_Ver_Byte10_02 : 8|8@1+ (1,0) [0|255] ""  PC
 SG_ M2P_Cfg4_HW_Ver_Byte11_02 : 16|8@1+ (1,0) [0|255] ""  PC
 SG_ M2P_Cfg4_HW_Ver_Byte12_02 : 24|8@1+ (1,0) [0|255] ""  PC
 SG_ M2P_Cfg4_HW_Ver_Byte13_02 : 32|8@1+ (1,0) [0|255] ""  PC
 SG_ M2P_Cfg4_HW_Ver_Byte14_02 : 40|8@1+ (1,0) [0|255] ""  PC
 SG_ M2P_Cfg4_HW_Ver_Byte15_02 : 48|8@1+ (1,0) [0|255] ""  PC
 SG_ M2P_Cfg4_HW_Ver_Byte16_02 : 56|8@1+ (1,0) [0|255] ""  PC

BO_ 2416307859 M2P_Cfg4__03: 8 MBMU
 SG_ M2P_Cfg4_HW_Ver_Byte9_03 : 0|8@1+ (1,0) [0|255] ""  PC
 SG_ M2P_Cfg4_HW_Ver_Byte10_03 : 8|8@1+ (1,0) [0|255] ""  PC
 SG_ M2P_Cfg4_HW_Ver_Byte11_03 : 16|8@1+ (1,0) [0|255] ""  PC
 SG_ M2P_Cfg4_HW_Ver_Byte12_03 : 24|8@1+ (1,0) [0|255] ""  PC
 SG_ M2P_Cfg4_HW_Ver_Byte13_03 : 32|8@1+ (1,0) [0|255] ""  PC
 SG_ M2P_Cfg4_HW_Ver_Byte14_03 : 40|8@1+ (1,0) [0|255] ""  PC
 SG_ M2P_Cfg4_HW_Ver_Byte15_03 : 48|8@1+ (1,0) [0|255] ""  PC
 SG_ M2P_Cfg4_HW_Ver_Byte16_03 : 56|8@1+ (1,0) [0|255] ""  PC

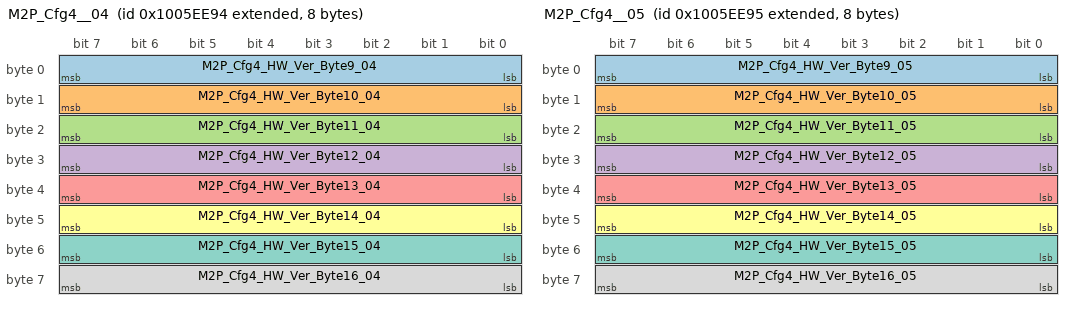
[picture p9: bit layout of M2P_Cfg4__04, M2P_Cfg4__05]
BO_ 2416307860 M2P_Cfg4__04: 8 MBMU
 SG_ M2P_Cfg4_HW_Ver_Byte9_04 : 0|8@1+ (1,0) [0|255] ""  PC
 SG_ M2P_Cfg4_HW_Ver_Byte10_04 : 8|8@1+ (1,0) [0|255] ""  PC
 SG_ M2P_Cfg4_HW_Ver_Byte11_04 : 16|8@1+ (1,0) [0|255] ""  PC
 SG_ M2P_Cfg4_HW_Ver_Byte12_04 : 24|8@1+ (1,0) [0|255] ""  PC
 SG_ M2P_Cfg4_HW_Ver_Byte13_04 : 32|8@1+ (1,0) [0|255] ""  PC
 SG_ M2P_Cfg4_HW_Ver_Byte14_04 : 40|8@1+ (1,0) [0|255] ""  PC
 SG_ M2P_Cfg4_HW_Ver_Byte15_04 : 48|8@1+ (1,0) [0|255] ""  PC
 SG_ M2P_Cfg4_HW_Ver_Byte16_04 : 56|8@1+ (1,0) [0|255] ""  PC

BO_ 2416307861 M2P_Cfg4__05: 8 MBMU
 SG_ M2P_Cfg4_HW_Ver_Byte9_05 : 0|8@1+ (1,0) [0|255] ""  PC
 SG_ M2P_Cfg4_HW_Ver_Byte10_05 : 8|8@1+ (1,0) [0|255] ""  PC
 SG_ M2P_Cfg4_HW_Ver_Byte11_05 : 16|8@1+ (1,0) [0|255] ""  PC
 SG_ M2P_Cfg4_HW_Ver_Byte12_05 : 24|8@1+ (1,0) [0|255] ""  PC
 SG_ M2P_Cfg4_HW_Ver_Byte13_05 : 32|8@1+ (1,0) [0|255] ""  PC
 SG_ M2P_Cfg4_HW_Ver_Byte14_05 : 40|8@1+ (1,0) [0|255] ""  PC
 SG_ M2P_Cfg4_HW_Ver_Byte15_05 : 48|8@1+ (1,0) [0|255] ""  PC
 SG_ M2P_Cfg4_HW_Ver_Byte16_05 : 56|8@1+ (1,0) [0|255] ""  PC

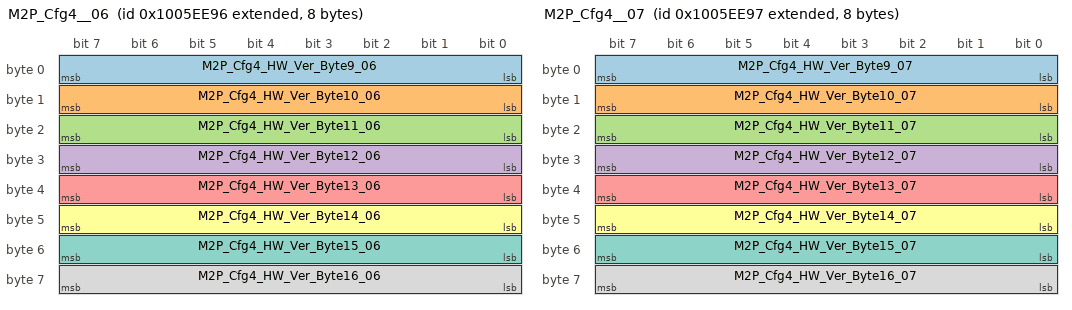
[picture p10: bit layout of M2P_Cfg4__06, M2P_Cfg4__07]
BO_ 2416307862 M2P_Cfg4__06: 8 MBMU
 SG_ M2P_Cfg4_HW_Ver_Byte9_06 : 0|8@1+ (1,0) [0|255] ""  PC
 SG_ M2P_Cfg4_HW_Ver_Byte10_06 : 8|8@1+ (1,0) [0|255] ""  PC
 SG_ M2P_Cfg4_HW_Ver_Byte11_06 : 16|8@1+ (1,0) [0|255] ""  PC
 SG_ M2P_Cfg4_HW_Ver_Byte12_06 : 24|8@1+ (1,0) [0|255] ""  PC
 SG_ M2P_Cfg4_HW_Ver_Byte13_06 : 32|8@1+ (1,0) [0|255] ""  PC
 SG_ M2P_Cfg4_HW_Ver_Byte14_06 : 40|8@1+ (1,0) [0|255] ""  PC
 SG_ M2P_Cfg4_HW_Ver_Byte15_06 : 48|8@1+ (1,0) [0|255] ""  PC
 SG_ M2P_Cfg4_HW_Ver_Byte16_06 : 56|8@1+ (1,0) [0|255] ""  PC

BO_ 2416307863 M2P_Cfg4__07: 8 MBMU
 SG_ M2P_Cfg4_HW_Ver_Byte9_07 : 0|8@1+ (1,0) [0|255] ""  PC
 SG_ M2P_Cfg4_HW_Ver_Byte10_07 : 8|8@1+ (1,0) [0|255] ""  PC
 SG_ M2P_Cfg4_HW_Ver_Byte11_07 : 16|8@1+ (1,0) [0|255] ""  PC
 SG_ M2P_Cfg4_HW_Ver_Byte12_07 : 24|8@1+ (1,0) [0|255] ""  PC
 SG_ M2P_Cfg4_HW_Ver_Byte13_07 : 32|8@1+ (1,0) [0|255] ""  PC
 SG_ M2P_Cfg4_HW_Ver_Byte14_07 : 40|8@1+ (1,0) [0|255] ""  PC
 SG_ M2P_Cfg4_HW_Ver_Byte15_07 : 48|8@1+ (1,0) [0|255] ""  PC
 SG_ M2P_Cfg4_HW_Ver_Byte16_07 : 56|8@1+ (1,0) [0|255] ""  PC

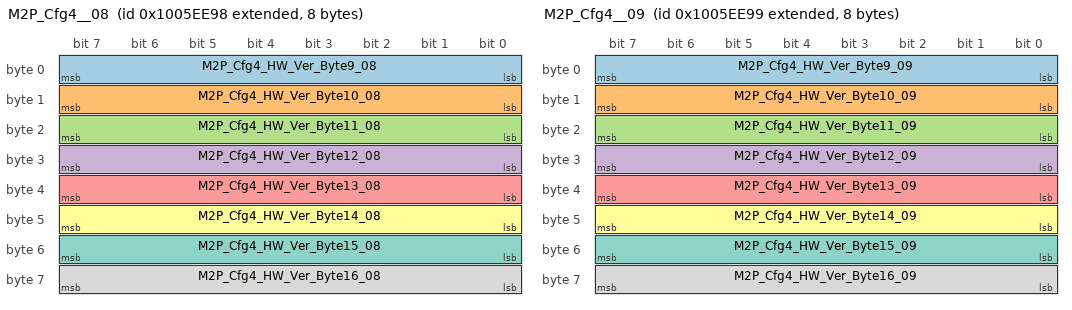
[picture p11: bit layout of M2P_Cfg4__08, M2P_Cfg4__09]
BO_ 2416307864 M2P_Cfg4__08: 8 MBMU
 SG_ M2P_Cfg4_HW_Ver_Byte9_08 : 0|8@1+ (1,0) [0|255] ""  PC
 SG_ M2P_Cfg4_HW_Ver_Byte10_08 : 8|8@1+ (1,0) [0|255] ""  PC
 SG_ M2P_Cfg4_HW_Ver_Byte11_08 : 16|8@1+ (1,0) [0|255] ""  PC
 SG_ M2P_Cfg4_HW_Ver_Byte12_08 : 24|8@1+ (1,0) [0|255] ""  PC
 SG_ M2P_Cfg4_HW_Ver_Byte13_08 : 32|8@1+ (1,0) [0|255] ""  PC
 SG_ M2P_Cfg4_HW_Ver_Byte14_08 : 40|8@1+ (1,0) [0|255] ""  PC
 SG_ M2P_Cfg4_HW_Ver_Byte15_08 : 48|8@1+ (1,0) [0|255] ""  PC
 SG_ M2P_Cfg4_HW_Ver_Byte16_08 : 56|8@1+ (1,0) [0|255] ""  PC

BO_ 2416307865 M2P_Cfg4__09: 8 MBMU
 SG_ M2P_Cfg4_HW_Ver_Byte9_09 : 0|8@1+ (1,0) [0|255] ""  PC
 SG_ M2P_Cfg4_HW_Ver_Byte10_09 : 8|8@1+ (1,0) [0|255] ""  PC
 SG_ M2P_Cfg4_HW_Ver_Byte11_09 : 16|8@1+ (1,0) [0|255] ""  PC
 SG_ M2P_Cfg4_HW_Ver_Byte12_09 : 24|8@1+ (1,0) [0|255] ""  PC
 SG_ M2P_Cfg4_HW_Ver_Byte13_09 : 32|8@1+ (1,0) [0|255] ""  PC
 SG_ M2P_Cfg4_HW_Ver_Byte14_09 : 40|8@1+ (1,0) [0|255] ""  PC
 SG_ M2P_Cfg4_HW_Ver_Byte15_09 : 48|8@1+ (1,0) [0|255] ""  PC
 SG_ M2P_Cfg4_HW_Ver_Byte16_09 : 56|8@1+ (1,0) [0|255] ""  PC

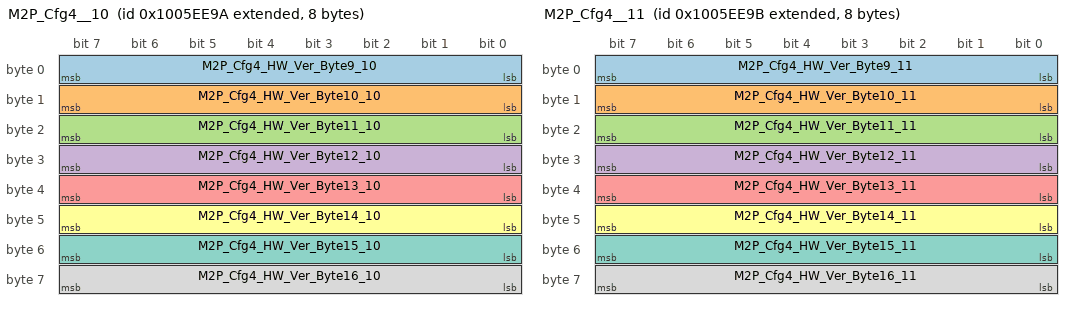
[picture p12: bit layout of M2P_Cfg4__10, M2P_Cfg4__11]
BO_ 2416307866 M2P_Cfg4__10: 8 MBMU
 SG_ M2P_Cfg4_HW_Ver_Byte9_10 : 0|8@1+ (1,0) [0|255] ""  PC
 SG_ M2P_Cfg4_HW_Ver_Byte10_10 : 8|8@1+ (1,0) [0|255] ""  PC
 SG_ M2P_Cfg4_HW_Ver_Byte11_10 : 16|8@1+ (1,0) [0|255] ""  PC
 SG_ M2P_Cfg4_HW_Ver_Byte12_10 : 24|8@1+ (1,0) [0|255] ""  PC
 SG_ M2P_Cfg4_HW_Ver_Byte13_10 : 32|8@1+ (1,0) [0|255] ""  PC
 SG_ M2P_Cfg4_HW_Ver_Byte14_10 : 40|8@1+ (1,0) [0|255] ""  PC
 SG_ M2P_Cfg4_HW_Ver_Byte15_10 : 48|8@1+ (1,0) [0|255] ""  PC
 SG_ M2P_Cfg4_HW_Ver_Byte16_10 : 56|8@1+ (1,0) [0|255] ""  PC

BO_ 2416307867 M2P_Cfg4__11: 8 MBMU
 SG_ M2P_Cfg4_HW_Ver_Byte9_11 : 0|8@1+ (1,0) [0|255] ""  PC
 SG_ M2P_Cfg4_HW_Ver_Byte10_11 : 8|8@1+ (1,0) [0|255] ""  PC
 SG_ M2P_Cfg4_HW_Ver_Byte11_11 : 16|8@1+ (1,0) [0|255] ""  PC
 SG_ M2P_Cfg4_HW_Ver_Byte12_11 : 24|8@1+ (1,0) [0|255] ""  PC
 SG_ M2P_Cfg4_HW_Ver_Byte13_11 : 32|8@1+ (1,0) [0|255] ""  PC
 SG_ M2P_Cfg4_HW_Ver_Byte14_11 : 40|8@1+ (1,0) [0|255] ""  PC
 SG_ M2P_Cfg4_HW_Ver_Byte15_11 : 48|8@1+ (1,0) [0|255] ""  PC
 SG_ M2P_Cfg4_HW_Ver_Byte16_11 : 56|8@1+ (1,0) [0|255] ""  PC

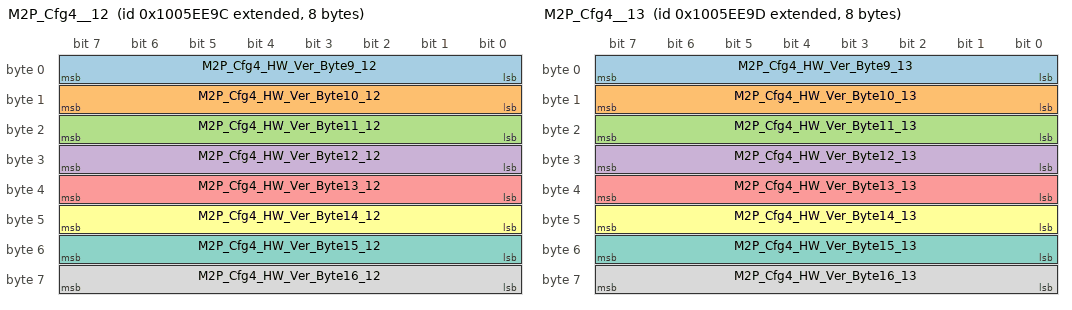
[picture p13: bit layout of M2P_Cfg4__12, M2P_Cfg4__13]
BO_ 2416307868 M2P_Cfg4__12: 8 MBMU
 SG_ M2P_Cfg4_HW_Ver_Byte9_12 : 0|8@1+ (1,0) [0|255] ""  PC
 SG_ M2P_Cfg4_HW_Ver_Byte10_12 : 8|8@1+ (1,0) [0|255] ""  PC
 SG_ M2P_Cfg4_HW_Ver_Byte11_12 : 16|8@1+ (1,0) [0|255] ""  PC
 SG_ M2P_Cfg4_HW_Ver_Byte12_12 : 24|8@1+ (1,0) [0|255] ""  PC
 SG_ M2P_Cfg4_HW_Ver_Byte13_12 : 32|8@1+ (1,0) [0|255] ""  PC
 SG_ M2P_Cfg4_HW_Ver_Byte14_12 : 40|8@1+ (1,0) [0|255] ""  PC
 SG_ M2P_Cfg4_HW_Ver_Byte15_12 : 48|8@1+ (1,0) [0|255] ""  PC
 SG_ M2P_Cfg4_HW_Ver_Byte16_12 : 56|8@1+ (1,0) [0|255] ""  PC

BO_ 2416307869 M2P_Cfg4__13: 8 MBMU
 SG_ M2P_Cfg4_HW_Ver_Byte9_13 : 0|8@1+ (1,0) [0|255] ""  PC
 SG_ M2P_Cfg4_HW_Ver_Byte10_13 : 8|8@1+ (1,0) [0|255] ""  PC
 SG_ M2P_Cfg4_HW_Ver_Byte11_13 : 16|8@1+ (1,0) [0|255] ""  PC
 SG_ M2P_Cfg4_HW_Ver_Byte12_13 : 24|8@1+ (1,0) [0|255] ""  PC
 SG_ M2P_Cfg4_HW_Ver_Byte13_13 : 32|8@1+ (1,0) [0|255] ""  PC
 SG_ M2P_Cfg4_HW_Ver_Byte14_13 : 40|8@1+ (1,0) [0|255] ""  PC
 SG_ M2P_Cfg4_HW_Ver_Byte15_13 : 48|8@1+ (1,0) [0|255] ""  PC
 SG_ M2P_Cfg4_HW_Ver_Byte16_13 : 56|8@1+ (1,0) [0|255] ""  PC

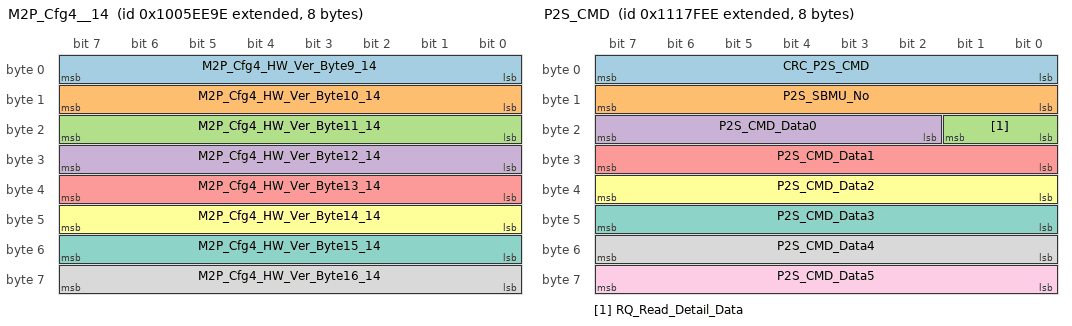
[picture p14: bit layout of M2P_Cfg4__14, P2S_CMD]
BO_ 2416307870 M2P_Cfg4__14: 8 MBMU
 SG_ M2P_Cfg4_HW_Ver_Byte9_14 : 0|8@1+ (1,0) [0|255] ""  PC
 SG_ M2P_Cfg4_HW_Ver_Byte10_14 : 8|8@1+ (1,0) [0|255] ""  PC
 SG_ M2P_Cfg4_HW_Ver_Byte11_14 : 16|8@1+ (1,0) [0|255] ""  PC
 SG_ M2P_Cfg4_HW_Ver_Byte12_14 : 24|8@1+ (1,0) [0|255] ""  PC
 SG_ M2P_Cfg4_HW_Ver_Byte13_14 : 32|8@1+ (1,0) [0|255] ""  PC
 SG_ M2P_Cfg4_HW_Ver_Byte14_14 : 40|8@1+ (1,0) [0|255] ""  PC
 SG_ M2P_Cfg4_HW_Ver_Byte15_14 : 48|8@1+ (1,0) [0|255] ""  PC
 SG_ M2P_Cfg4_HW_Ver_Byte16_14 : 56|8@1+ (1,0) [0|255] ""  PC

BO_ 2416307871 M2P_Cfg4__15: 8 MBMU
 SG_ M2P_Cfg4_HW_Ver_Byte9_15 : 0|8@1+ (1,0) [0|255] ""  PC
 SG_ M2P_Cfg4_HW_Ver_Byte10_15 : 8|8@1+ (1,0) [0|255] ""  PC
 SG_ M2P_Cfg4_HW_Ver_Byte11_15 : 16|8@1+ (1,0) [0|255] ""  PC
 SG_ M2P_Cfg4_HW_Ver_Byte12_15 : 24|8@1+ (1,0) [0|255] ""  PC
 SG_ M2P_Cfg4_HW_Ver_Byte13_15 : 32|8@1+ (1,0) [0|255] ""  PC
 SG_ M2P_Cfg4_HW_Ver_Byte14_15 : 40|8@1+ (1,0) [0|255] ""  PC
 SG_ M2P_Cfg4_HW_Ver_Byte15_15 : 48|8@1+ (1,0) [0|255] ""  PC
 SG_ M2P_Cfg4_HW_Ver_Byte16_15 : 56|8@1+ (1,0) [0|255] ""  PC

BO_ 2416307872 M2P_Cfg4__16: 8 MBMU
 SG_ M2P_Cfg4_HW_Ver_Byte9_16 : 0|8@1+ (1,0) [0|255] ""  PC
 SG_ M2P_Cfg4_HW_Ver_Byte10_16 : 8|8@1+ (1,0) [0|255] ""  PC
 SG_ M2P_Cfg4_HW_Ver_Byte11_16 : 16|8@1+ (1,0) [0|255] ""  PC
 SG_ M2P_Cfg4_HW_Ver_Byte12_16 : 24|8@1+ (1,0) [0|255] ""  PC
 SG_ M2P_Cfg4_HW_Ver_Byte13_16 : 32|8@1+ (1,0) [0|255] ""  PC
 SG_ M2P_Cfg4_HW_Ver_Byte14_16 : 40|8@1+ (1,0) [0|255] ""  PC
 SG_ M2P_Cfg4_HW_Ver_Byte15_16 : 48|8@1+ (1,0) [0|255] ""  PC
 SG_ M2P_Cfg4_HW_Ver_Byte16_16 : 56|8@1+ (1,0) [0|255] ""  PC

BO_ 2416307873 M2P_Cfg4__17: 8 MBMU
 SG_ M2P_Cfg4_HW_Ver_Byte9_17 : 0|8@1+ (1,0) [0|255] ""  PC
 SG_ M2P_Cfg4_HW_Ver_Byte10_17 : 8|8@1+ (1,0) [0|255] ""  PC
 SG_ M2P_Cfg4_HW_Ver_Byte11_17 : 16|8@1+ (1,0) [0|255] ""  PC
 SG_ M2P_Cfg4_HW_Ver_Byte12_17 : 24|8@1+ (1,0) [0|255] ""  PC
 SG_ M2P_Cfg4_HW_Ver_Byte13_17 : 32|8@1+ (1,0) [0|255] ""  PC
 SG_ M2P_Cfg4_HW_Ver_Byte14_17 : 40|8@1+ (1,0) [0|255] ""  PC
 SG_ M2P_Cfg4_HW_Ver_Byte15_17 : 48|8@1+ (1,0) [0|255] ""  PC
 SG_ M2P_Cfg4_HW_Ver_Byte16_17 : 56|8@1+ (1,0) [0|255] ""  PC

BO_ 2416307874 M2P_Cfg4__18: 8 MBMU
 SG_ M2P_Cfg4_HW_Ver_Byte9_18 : 0|8@1+ (1,0) [0|255] ""  PC
 SG_ M2P_Cfg4_HW_Ver_Byte10_18 : 8|8@1+ (1,0) [0|255] ""  PC
 SG_ M2P_Cfg4_HW_Ver_Byte11_18 : 16|8@1+ (1,0) [0|255] ""  PC
 SG_ M2P_Cfg4_HW_Ver_Byte12_18 : 24|8@1+ (1,0) [0|255] ""  PC
 SG_ M2P_Cfg4_HW_Ver_Byte13_18 : 32|8@1+ (1,0) [0|255] ""  PC
 SG_ M2P_Cfg4_HW_Ver_Byte14_18 : 40|8@1+ (1,0) [0|255] ""  PC
 SG_ M2P_Cfg4_HW_Ver_Byte15_18 : 48|8@1+ (1,0) [0|255] ""  PC
 SG_ M2P_Cfg4_HW_Ver_Byte16_18 : 56|8@1+ (1,0) [0|255] ""  PC

BO_ 2416307875 M2P_Cfg4__19: 8 MBMU
 SG_ M2P_Cfg4_HW_Ver_Byte9_19 : 0|8@1+ (1,0) [0|255] ""  PC
 SG_ M2P_Cfg4_HW_Ver_Byte10_19 : 8|8@1+ (1,0) [0|255] ""  PC
 SG_ M2P_Cfg4_HW_Ver_Byte11_19 : 16|8@1+ (1,0) [0|255] ""  PC
 SG_ M2P_Cfg4_HW_Ver_Byte12_19 : 24|8@1+ (1,0) [0|255] ""  PC
 SG_ M2P_Cfg4_HW_Ver_Byte13_19 : 32|8@1+ (1,0) [0|255] ""  PC
 SG_ M2P_Cfg4_HW_Ver_Byte14_19 : 40|8@1+ (1,0) [0|255] ""  PC
 SG_ M2P_Cfg4_HW_Ver_Byte15_19 : 48|8@1+ (1,0) [0|255] ""  PC
 SG_ M2P_Cfg4_HW_Ver_Byte16_19 : 56|8@1+ (1,0) [0|255] ""  PC

BO_ 2416307876 M2P_Cfg4__20: 8 MBMU
 SG_ M2P_Cfg4_HW_Ver_Byte9_20 : 0|8@1+ (1,0) [0|255] ""  PC
 SG_ M2P_Cfg4_HW_Ver_Byte10_20 : 8|8@1+ (1,0) [0|255] ""  PC
 SG_ M2P_Cfg4_HW_Ver_Byte11_20 : 16|8@1+ (1,0) [0|255] ""  PC
 SG_ M2P_Cfg4_HW_Ver_Byte12_20 : 24|8@1+ (1,0) [0|255] ""  PC
 SG_ M2P_Cfg4_HW_Ver_Byte13_20 : 32|8@1+ (1,0) [0|255] ""  PC
 SG_ M2P_Cfg4_HW_Ver_Byte14_20 : 40|8@1+ (1,0) [0|255] ""  PC
 SG_ M2P_Cfg4_HW_Ver_Byte15_20 : 48|8@1+ (1,0) [0|255] ""  PC
 SG_ M2P_Cfg4_HW_Ver_Byte16_20 : 56|8@1+ (1,0) [0|255] ""  PC

BO_ 2416307877 M2P_Cfg4__21: 8 MBMU
 SG_ M2P_Cfg4_HW_Ver_Byte9_21 : 0|8@1+ (1,0) [0|255] ""  PC
 SG_ M2P_Cfg4_HW_Ver_Byte10_21 : 8|8@1+ (1,0) [0|255] ""  PC
 SG_ M2P_Cfg4_HW_Ver_Byte11_21 : 16|8@1+ (1,0) [0|255] ""  PC
 SG_ M2P_Cfg4_HW_Ver_Byte12_21 : 24|8@1+ (1,0) [0|255] ""  PC
 SG_ M2P_Cfg4_HW_Ver_Byte13_21 : 32|8@1+ (1,0) [0|255] ""  PC
 SG_ M2P_Cfg4_HW_Ver_Byte14_21 : 40|8@1+ (1,0) [0|255] ""  PC
 SG_ M2P_Cfg4_HW_Ver_Byte15_21 : 48|8@1+ (1,0) [0|255] ""  PC
 SG_ M2P_Cfg4_HW_Ver_Byte16_21 : 56|8@1+ (1,0) [0|255] ""  PC

BO_ 2416307878 M2P_Cfg4__22: 8 MBMU
 SG_ M2P_Cfg4_HW_Ver_Byte9_22 : 0|8@1+ (1,0) [0|255] ""  PC
 SG_ M2P_Cfg4_HW_Ver_Byte10_22 : 8|8@1+ (1,0) [0|255] ""  PC
 SG_ M2P_Cfg4_HW_Ver_Byte11_22 : 16|8@1+ (1,0) [0|255] ""  PC
 SG_ M2P_Cfg4_HW_Ver_Byte12_22 : 24|8@1+ (1,0) [0|255] ""  PC
 SG_ M2P_Cfg4_HW_Ver_Byte13_22 : 32|8@1+ (1,0) [0|255] ""  PC
 SG_ M2P_Cfg4_HW_Ver_Byte14_22 : 40|8@1+ (1,0) [0|255] ""  PC
 SG_ M2P_Cfg4_HW_Ver_Byte15_22 : 48|8@1+ (1,0) [0|255] ""  PC
 SG_ M2P_Cfg4_HW_Ver_Byte16_22 : 56|8@1+ (1,0) [0|255] ""  PC

BO_ 2416307879 M2P_Cfg4__23: 8 MBMU
 SG_ M2P_Cfg4_HW_Ver_Byte9_23 : 0|8@1+ (1,0) [0|255] ""  PC
 SG_ M2P_Cfg4_HW_Ver_Byte10_23 : 8|8@1+ (1,0) [0|255] ""  PC
 SG_ M2P_Cfg4_HW_Ver_Byte11_23 : 16|8@1+ (1,0) [0|255] ""  PC
 SG_ M2P_Cfg4_HW_Ver_Byte12_23 : 24|8@1+ (1,0) [0|255] ""  PC
 SG_ M2P_Cfg4_HW_Ver_Byte13_23 : 32|8@1+ (1,0) [0|255] ""  PC
 SG_ M2P_Cfg4_HW_Ver_Byte14_23 : 40|8@1+ (1,0) [0|255] ""  PC
 SG_ M2P_Cfg4_HW_Ver_Byte15_23 : 48|8@1+ (1,0) [0|255] ""  PC
 SG_ M2P_Cfg4_HW_Ver_Byte16_23 : 56|8@1+ (1,0) [0|255] ""  PC

BO_ 2416307880 M2P_Cfg4__24: 8 MBMU
 SG_ M2P_Cfg4_HW_Ver_Byte9_24 : 0|8@1+ (1,0) [0|255] ""  PC
 SG_ M2P_Cfg4_HW_Ver_Byte10_24 : 8|8@1+ (1,0) [0|255] ""  PC
 SG_ M2P_Cfg4_HW_Ver_Byte11_24 : 16|8@1+ (1,0) [0|255] ""  PC
 SG_ M2P_Cfg4_HW_Ver_Byte12_24 : 24|8@1+ (1,0) [0|255] ""  PC
 SG_ M2P_Cfg4_HW_Ver_Byte13_24 : 32|8@1+ (1,0) [0|255] ""  PC
 SG_ M2P_Cfg4_HW_Ver_Byte14_24 : 40|8@1+ (1,0) [0|255] ""  PC
 SG_ M2P_Cfg4_HW_Ver_Byte15_24 : 48|8@1+ (1,0) [0|255] ""  PC
 SG_ M2P_Cfg4_HW_Ver_Byte16_24 : 56|8@1+ (1,0) [0|255] ""  PC

BO_ 2416307881 M2P_Cfg4__25: 8 MBMU
 SG_ M2P_Cfg4_HW_Ver_Byte9_25 : 0|8@1+ (1,0) [0|255] ""  PC
 SG_ M2P_Cfg4_HW_Ver_Byte10_25 : 8|8@1+ (1,0) [0|255] ""  PC
 SG_ M2P_Cfg4_HW_Ver_Byte11_25 : 16|8@1+ (1,0) [0|255] ""  PC
 SG_ M2P_Cfg4_HW_Ver_Byte12_25 : 24|8@1+ (1,0) [0|255] ""  PC
 SG_ M2P_Cfg4_HW_Ver_Byte13_25 : 32|8@1+ (1,0) [0|255] ""  PC
 SG_ M2P_Cfg4_HW_Ver_Byte14_25 : 40|8@1+ (1,0) [0|255] ""  PC
 SG_ M2P_Cfg4_HW_Ver_Byte15_25 : 48|8@1+ (1,0) [0|255] ""  PC
 SG_ M2P_Cfg4_HW_Ver_Byte16_25 : 56|8@1+ (1,0) [0|255] ""  PC

BO_ 2416307882 M2P_Cfg4__26: 8 MBMU
 SG_ M2P_Cfg4_HW_Ver_Byte9_26 : 0|8@1+ (1,0) [0|255] ""  PC
 SG_ M2P_Cfg4_HW_Ver_Byte10_26 : 8|8@1+ (1,0) [0|255] ""  PC
 SG_ M2P_Cfg4_HW_Ver_Byte11_26 : 16|8@1+ (1,0) [0|255] ""  PC
 SG_ M2P_Cfg4_HW_Ver_Byte12_26 : 24|8@1+ (1,0) [0|255] ""  PC
 SG_ M2P_Cfg4_HW_Ver_Byte13_26 : 32|8@1+ (1,0) [0|255] ""  PC
 SG_ M2P_Cfg4_HW_Ver_Byte14_26 : 40|8@1+ (1,0) [0|255] ""  PC
 SG_ M2P_Cfg4_HW_Ver_Byte15_26 : 48|8@1+ (1,0) [0|255] ""  PC
 SG_ M2P_Cfg4_HW_Ver_Byte16_26 : 56|8@1+ (1,0) [0|255] ""  PC

BO_ 2416307883 M2P_Cfg4__27: 8 MBMU
 SG_ M2P_Cfg4_HW_Ver_Byte9_27 : 0|8@1+ (1,0) [0|255] ""  PC
 SG_ M2P_Cfg4_HW_Ver_Byte10_27 : 8|8@1+ (1,0) [0|255] ""  PC
 SG_ M2P_Cfg4_HW_Ver_Byte11_27 : 16|8@1+ (1,0) [0|255] ""  PC
 SG_ M2P_Cfg4_HW_Ver_Byte12_27 : 24|8@1+ (1,0) [0|255] ""  PC
 SG_ M2P_Cfg4_HW_Ver_Byte13_27 : 32|8@1+ (1,0) [0|255] ""  PC
 SG_ M2P_Cfg4_HW_Ver_Byte14_27 : 40|8@1+ (1,0) [0|255] ""  PC
 SG_ M2P_Cfg4_HW_Ver_Byte15_27 : 48|8@1+ (1,0) [0|255] ""  PC
 SG_ M2P_Cfg4_HW_Ver_Byte16_27 : 56|8@1+ (1,0) [0|255] ""  PC

BO_ 2416307884 M2P_Cfg4__28: 8 MBMU
 SG_ M2P_Cfg4_HW_Ver_Byte9_28 : 0|8@1+ (1,0) [0|255] ""  PC
 SG_ M2P_Cfg4_HW_Ver_Byte10_28 : 8|8@1+ (1,0) [0|255] ""  PC
 SG_ M2P_Cfg4_HW_Ver_Byte11_28 : 16|8@1+ (1,0) [0|255] ""  PC
 SG_ M2P_Cfg4_HW_Ver_Byte12_28 : 24|8@1+ (1,0) [0|255] ""  PC
 SG_ M2P_Cfg4_HW_Ver_Byte13_28 : 32|8@1+ (1,0) [0|255] ""  PC
 SG_ M2P_Cfg4_HW_Ver_Byte14_28 : 40|8@1+ (1,0) [0|255] ""  PC
 SG_ M2P_Cfg4_HW_Ver_Byte15_28 : 48|8@1+ (1,0) [0|255] ""  PC
 SG_ M2P_Cfg4_HW_Ver_Byte16_28 : 56|8@1+ (1,0) [0|255] ""  PC

BO_ 2416307885 M2P_Cfg4__29: 8 MBMU
 SG_ M2P_Cfg4_HW_Ver_Byte9_29 : 0|8@1+ (1,0) [0|255] ""  PC
 SG_ M2P_Cfg4_HW_Ver_Byte10_29 : 8|8@1+ (1,0) [0|255] ""  PC
 SG_ M2P_Cfg4_HW_Ver_Byte11_29 : 16|8@1+ (1,0) [0|255] ""  PC
 SG_ M2P_Cfg4_HW_Ver_Byte12_29 : 24|8@1+ (1,0) [0|255] ""  PC
 SG_ M2P_Cfg4_HW_Ver_Byte13_29 : 32|8@1+ (1,0) [0|255] ""  PC
 SG_ M2P_Cfg4_HW_Ver_Byte14_29 : 40|8@1+ (1,0) [0|255] ""  PC
 SG_ M2P_Cfg4_HW_Ver_Byte15_29 : 48|8@1+ (1,0) [0|255] ""  PC
 SG_ M2P_Cfg4_HW_Ver_Byte16_29 : 56|8@1+ (1,0) [0|255] ""  PC

BO_ 2416307886 M2P_Cfg4__30: 8 MBMU
 SG_ M2P_Cfg4_HW_Ver_Byte9_30 : 0|8@1+ (1,0) [0|255] ""  PC
 SG_ M2P_Cfg4_HW_Ver_Byte10_30 : 8|8@1+ (1,0) [0|255] ""  PC
 SG_ M2P_Cfg4_HW_Ver_Byte11_30 : 16|8@1+ (1,0) [0|255] ""  PC
 SG_ M2P_Cfg4_HW_Ver_Byte12_30 : 24|8@1+ (1,0) [0|255] ""  PC
 SG_ M2P_Cfg4_HW_Ver_Byte13_30 : 32|8@1+ (1,0) [0|255] ""  PC
 SG_ M2P_Cfg4_HW_Ver_Byte14_30 : 40|8@1+ (1,0) [0|255] ""  PC
 SG_ M2P_Cfg4_HW_Ver_Byte15_30 : 48|8@1+ (1,0) [0|255] ""  PC
 SG_ M2P_Cfg4_HW_Ver_Byte16_30 : 56|8@1+ (1,0) [0|255] ""  PC

BO_ 2416307887 M2P_Cfg4__31: 8 MBMU
 SG_ M2P_Cfg4_HW_Ver_Byte9_31 : 0|8@1+ (1,0) [0|255] ""  PC
 SG_ M2P_Cfg4_HW_Ver_Byte10_31 : 8|8@1+ (1,0) [0|255] ""  PC
 SG_ M2P_Cfg4_HW_Ver_Byte11_31 : 16|8@1+ (1,0) [0|255] ""  PC
 SG_ M2P_Cfg4_HW_Ver_Byte12_31 : 24|8@1+ (1,0) [0|255] ""  PC
 SG_ M2P_Cfg4_HW_Ver_Byte13_31 : 32|8@1+ (1,0) [0|255] ""  PC
 SG_ M2P_Cfg4_HW_Ver_Byte14_31 : 40|8@1+ (1,0) [0|255] ""  PC
 SG_ M2P_Cfg4_HW_Ver_Byte15_31 : 48|8@1+ (1,0) [0|255] ""  PC
 SG_ M2P_Cfg4_HW_Ver_Byte16_31 : 56|8@1+ (1,0) [0|255] ""  PC

BO_ 2416373393 M2P_Cfg5__01: 8 MBMU
 SG_ M2P_Cfg5_MBMU_Add_01 : 0|8@1+ (1,0) [0|255] ""  PC
 SG_ S_U08_M2P_Cfg5_SBMUs_Num : 8|8@1+ (1,0) [0|255] ""  PC
 SG_ M2P_Cfg5_TnkRunAmnt_01 : 16|8@1+ (1,0) [0|255] ""  PC
 SG_ M2P_Cfg5_ProtocolA_Ver_01 : 24|8@1+ (1,0) [0|255] ""  PC

BO_ 2416373394 M2P_Cfg5__02: 8 MBMU
 SG_ M2P_Cfg5_MBMU_Add_02 : 0|8@1+ (1,0) [0|255] ""  PC
 SG_ S_U08_M2P_Cfg5_SBMUs_Num : 8|8@1+ (1,0) [0|255] ""  PC
 SG_ M2P_Cfg5_TnkRunAmnt_02 : 16|8@1+ (1,0) [0|255] ""  PC
 SG_ M2P_Cfg5_ProtocolA_Ver_02 : 24|8@1+ (1,0) [0|255] ""  PC

BO_ 2416373395 M2P_Cfg5__03: 8 MBMU
 SG_ M2P_Cfg5_MBMU_Add_03 : 0|8@1+ (1,0) [0|255] ""  PC
 SG_ S_U08_M2P_Cfg5_SBMUs_Num : 8|8@1+ (1,0) [0|255] ""  PC
 SG_ M2P_Cfg5_TnkRunAmnt_03 : 16|8@1+ (1,0) [0|255] ""  PC
 SG_ M2P_Cfg5_ProtocolA_Ver_03 : 24|8@1+ (1,0) [0|255] ""  PC

BO_ 2416373396 M2P_Cfg5__04: 8 MBMU
 SG_ M2P_Cfg5_MBMU_Add_04 : 0|8@1+ (1,0) [0|255] ""  PC
 SG_ S_U08_M2P_Cfg5_SBMUs_Num : 8|8@1+ (1,0) [0|255] ""  PC
 SG_ M2P_Cfg5_TnkRunAmnt_04 : 16|8@1+ (1,0) [0|255] ""  PC
 SG_ M2P_Cfg5_ProtocolA_Ver_04 : 24|8@1+ (1,0) [0|255] ""  PC

BO_ 2416373397 M2P_Cfg5__05: 8 MBMU
 SG_ M2P_Cfg5_MBMU_Add_05 : 0|8@1+ (1,0) [0|255] ""  PC
 SG_ S_U08_M2P_Cfg5_SBMUs_Num : 8|8@1+ (1,0) [0|255] ""  PC
 SG_ M2P_Cfg5_TnkRunAmnt_05 : 16|8@1+ (1,0) [0|255] ""  PC
 SG_ M2P_Cfg5_ProtocolA_Ver_05 : 24|8@1+ (1,0) [0|255] ""  PC

BO_ 2416373398 M2P_Cfg5__06: 8 MBMU
 SG_ M2P_Cfg5_MBMU_Add_06 : 0|8@1+ (1,0) [0|255] ""  PC
 SG_ S_U08_M2P_Cfg5_SBMUs_Num : 8|8@1+ (1,0) [0|255] ""  PC
 SG_ M2P_Cfg5_TnkRunAmnt_06 : 16|8@1+ (1,0) [0|255] ""  PC
 SG_ M2P_Cfg5_ProtocolA_Ver_06 : 24|8@1+ (1,0) [0|255] ""  PC

BO_ 2416373399 M2P_Cfg5__07: 8 MBMU
 SG_ M2P_Cfg5_MBMU_Add_07 : 0|8@1+ (1,0) [0|255] ""  PC
 SG_ S_U08_M2P_Cfg5_SBMUs_Num : 8|8@1+ (1,0) [0|255] ""  PC
 SG_ M2P_Cfg5_TnkRunAmnt_07 : 16|8@1+ (1,0) [0|255] ""  PC
 SG_ M2P_Cfg5_ProtocolA_Ver_07 : 24|8@1+ (1,0) [0|255] ""  PC

BO_ 2416373400 M2P_Cfg5__08: 8 MBMU
 SG_ M2P_Cfg5_MBMU_Add_08 : 0|8@1+ (1,0) [0|255] ""  PC
 SG_ S_U08_M2P_Cfg5_SBMUs_Num : 8|8@1+ (1,0) [0|255] ""  PC
 SG_ M2P_Cfg5_TnkRunAmnt_08 : 16|8@1+ (1,0) [0|255] ""  PC
 SG_ M2P_Cfg5_ProtocolA_Ver_08 : 24|8@1+ (1,0) [0|255] ""  PC

BO_ 2416373401 M2P_Cfg5__09: 8 MBMU
 SG_ M2P_Cfg5_MBMU_Add_09 : 0|8@1+ (1,0) [0|255] ""  PC
 SG_ S_U08_M2P_Cfg5_SBMUs_Num : 8|8@1+ (1,0) [0|255] ""  PC
 SG_ M2P_Cfg5_TnkRunAmnt_09 : 16|8@1+ (1,0) [0|255] ""  PC
 SG_ M2P_Cfg5_ProtocolA_Ver_09 : 24|8@1+ (1,0) [0|255] ""  PC

BO_ 2416373402 M2P_Cfg5__10: 8 MBMU
 SG_ M2P_Cfg5_MBMU_Add_10 : 0|8@1+ (1,0) [0|255] ""  PC
 SG_ S_U08_M2P_Cfg5_SBMUs_Num : 8|8@1+ (1,0) [0|255] ""  PC
 SG_ M2P_Cfg5_TnkRunAmnt_10 : 16|8@1+ (1,0) [0|255] ""  PC
 SG_ M2P_Cfg5_ProtocolA_Ver_10 : 24|8@1+ (1,0) [0|255] ""  PC

BO_ 2416373403 M2P_Cfg5__11: 8 MBMU
 SG_ M2P_Cfg5_MBMU_Add_11 : 0|8@1+ (1,0) [0|255] ""  PC
 SG_ S_U08_M2P_Cfg5_SBMUs_Num : 8|8@1+ (1,0) [0|255] ""  PC
 SG_ M2P_Cfg5_TnkRunAmnt_11 : 16|8@1+ (1,0) [0|255] ""  PC
 SG_ M2P_Cfg5_ProtocolA_Ver_11 : 24|8@1+ (1,0) [0|255] ""  PC

BO_ 2416373404 M2P_Cfg5__12: 8 MBMU
 SG_ M2P_Cfg5_MBMU_Add_12 : 0|8@1+ (1,0) [0|255] ""  PC
 SG_ S_U08_M2P_Cfg5_SBMUs_Num : 8|8@1+ (1,0) [0|255] ""  PC
 SG_ M2P_Cfg5_TnkRunAmnt_12 : 16|8@1+ (1,0) [0|255] ""  PC
 SG_ M2P_Cfg5_ProtocolA_Ver_12 : 24|8@1+ (1,0) [0|255] ""  PC

BO_ 2416373405 M2P_Cfg5__13: 8 MBMU
 SG_ M2P_Cfg5_MBMU_Add_13 : 0|8@1+ (1,0) [0|255] ""  PC
 SG_ S_U08_M2P_Cfg5_SBMUs_Num : 8|8@1+ (1,0) [0|255] ""  PC
 SG_ M2P_Cfg5_TnkRunAmnt_13 : 16|8@1+ (1,0) [0|255] ""  PC
 SG_ M2P_Cfg5_ProtocolA_Ver_13 : 24|8@1+ (1,0) [0|255] ""  PC

BO_ 2416373406 M2P_Cfg5__14: 8 MBMU
 SG_ M2P_Cfg5_MBMU_Add_14 : 0|8@1+ (1,0) [0|255] ""  PC
 SG_ S_U08_M2P_Cfg5_SBMUs_Num : 8|8@1+ (1,0) [0|255] ""  PC
 SG_ M2P_Cfg5_TnkRunAmnt_14 : 16|8@1+ (1,0) [0|255] ""  PC
 SG_ M2P_Cfg5_ProtocolA_Ver_14 : 24|8@1+ (1,0) [0|255] ""  PC

BO_ 2416373407 M2P_Cfg5__15: 8 MBMU
 SG_ M2P_Cfg5_MBMU_Add_15 : 0|8@1+ (1,0) [0|255] ""  PC
 SG_ S_U08_M2P_Cfg5_SBMUs_Num : 8|8@1+ (1,0) [0|255] ""  PC
 SG_ M2P_Cfg5_TnkRunAmnt_15 : 16|8@1+ (1,0) [0|255] ""  PC
 SG_ M2P_Cfg5_ProtocolA_Ver_15 : 24|8@1+ (1,0) [0|255] ""  PC

BO_ 2416373408 M2P_Cfg5__16: 8 MBMU
 SG_ M2P_Cfg5_MBMU_Add_16 : 0|8@1+ (1,0) [0|255] ""  PC
 SG_ S_U08_M2P_Cfg5_SBMUs_Num : 8|8@1+ (1,0) [0|255] ""  PC
 SG_ M2P_Cfg5_TnkRunAmnt_16 : 16|8@1+ (1,0) [0|255] ""  PC
 SG_ M2P_Cfg5_ProtocolA_Ver_16 : 24|8@1+ (1,0) [0|255] ""  PC

BO_ 2416373409 M2P_Cfg5__17: 8 MBMU
 SG_ M2P_Cfg5_MBMU_Add_17 : 0|8@1+ (1,0) [0|255] ""  PC
 SG_ S_U08_M2P_Cfg5_SBMUs_Num : 8|8@1+ (1,0) [0|255] ""  PC
 SG_ M2P_Cfg5_TnkRunAmnt_17 : 16|8@1+ (1,0) [0|255] ""  PC
 SG_ M2P_Cfg5_ProtocolA_Ver_17 : 24|8@1+ (1,0) [0|255] ""  PC

BO_ 2416373410 M2P_Cfg5__18: 8 MBMU
 SG_ M2P_Cfg5_MBMU_Add_18 : 0|8@1+ (1,0) [0|255] ""  PC
 SG_ S_U08_M2P_Cfg5_SBMUs_Num : 8|8@1+ (1,0) [0|255] ""  PC
 SG_ M2P_Cfg5_TnkRunAmnt_18 : 16|8@1+ (1,0) [0|255] ""  PC
 SG_ M2P_Cfg5_ProtocolA_Ver_18 : 24|8@1+ (1,0) [0|255] ""  PC

BO_ 2416373411 M2P_Cfg5__19: 8 MBMU
 SG_ M2P_Cfg5_MBMU_Add_19 : 0|8@1+ (1,0) [0|255] ""  PC
 SG_ S_U08_M2P_Cfg5_SBMUs_Num : 8|8@1+ (1,0) [0|255] ""  PC
 SG_ M2P_Cfg5_TnkRunAmnt_19 : 16|8@1+ (1,0) [0|255] ""  PC
 SG_ M2P_Cfg5_ProtocolA_Ver_19 : 24|8@1+ (1,0) [0|255] ""  PC

BO_ 2416373412 M2P_Cfg5__20: 8 MBMU
 SG_ M2P_Cfg5_MBMU_Add_20 : 0|8@1+ (1,0) [0|255] ""  PC
 SG_ S_U08_M2P_Cfg5_SBMUs_Num : 8|8@1+ (1,0) [0|255] ""  PC
 SG_ M2P_Cfg5_TnkRunAmnt_20 : 16|8@1+ (1,0) [0|255] ""  PC
 SG_ M2P_Cfg5_ProtocolA_Ver_20 : 24|8@1+ (1,0) [0|255] ""  PC

BO_ 2416373413 M2P_Cfg5__21: 8 MBMU
 SG_ M2P_Cfg5_MBMU_Add_21 : 0|8@1+ (1,0) [0|255] ""  PC
 SG_ S_U08_M2P_Cfg5_SBMUs_Num : 8|8@1+ (1,0) [0|255] ""  PC
 SG_ M2P_Cfg5_TnkRunAmnt_21 : 16|8@1+ (1,0) [0|255] ""  PC
 SG_ M2P_Cfg5_ProtocolA_Ver_21 : 24|8@1+ (1,0) [0|255] ""  PC

BO_ 2416373414 M2P_Cfg5__22: 8 MBMU
 SG_ M2P_Cfg5_MBMU_Add_22 : 0|8@1+ (1,0) [0|255] ""  PC
 SG_ S_U08_M2P_Cfg5_SBMUs_Num : 8|8@1+ (1,0) [0|255] ""  PC
 SG_ M2P_Cfg5_TnkRunAmnt_22 : 16|8@1+ (1,0) [0|255] ""  PC
 SG_ M2P_Cfg5_ProtocolA_Ver_22 : 24|8@1+ (1,0) [0|255] ""  PC

BO_ 2416373415 M2P_Cfg5__23: 8 MBMU
 SG_ M2P_Cfg5_MBMU_Add_23 : 0|8@1+ (1,0) [0|255] ""  PC
 SG_ S_U08_M2P_Cfg5_SBMUs_Num : 8|8@1+ (1,0) [0|255] ""  PC
 SG_ M2P_Cfg5_TnkRunAmnt_23 : 16|8@1+ (1,0) [0|255] ""  PC
 SG_ M2P_Cfg5_ProtocolA_Ver_23 : 24|8@1+ (1,0) [0|255] ""  PC

BO_ 2416373416 M2P_Cfg5__24: 8 MBMU
 SG_ M2P_Cfg5_MBMU_Add_24 : 0|8@1+ (1,0) [0|255] ""  PC
 SG_ S_U08_M2P_Cfg5_SBMUs_Num : 8|8@1+ (1,0) [0|255] ""  PC
 SG_ M2P_Cfg5_TnkRunAmnt_24 : 16|8@1+ (1,0) [0|255] ""  PC
 SG_ M2P_Cfg5_ProtocolA_Ver_24 : 24|8@1+ (1,0) [0|255] ""  PC

BO_ 2416373417 M2P_Cfg5__25: 8 MBMU
 SG_ M2P_Cfg5_MBMU_Add_25 : 0|8@1+ (1,0) [0|255] ""  PC
 SG_ S_U08_M2P_Cfg5_SBMUs_Num : 8|8@1+ (1,0) [0|255] ""  PC
 SG_ M2P_Cfg5_TnkRunAmnt_25 : 16|8@1+ (1,0) [0|255] ""  PC
 SG_ M2P_Cfg5_ProtocolA_Ver_25 : 24|8@1+ (1,0) [0|255] ""  PC

BO_ 2416373418 M2P_Cfg5__26: 8 MBMU
 SG_ M2P_Cfg5_MBMU_Add_26 : 0|8@1+ (1,0) [0|255] ""  PC
 SG_ S_U08_M2P_Cfg5_SBMUs_Num : 8|8@1+ (1,0) [0|255] ""  PC
 SG_ M2P_Cfg5_TnkRunAmnt_26 : 16|8@1+ (1,0) [0|255] ""  PC
 SG_ M2P_Cfg5_ProtocolA_Ver_26 : 24|8@1+ (1,0) [0|255] ""  PC

BO_ 2416373419 M2P_Cfg5__27: 8 MBMU
 SG_ M2P_Cfg5_MBMU_Add_27 : 0|8@1+ (1,0) [0|255] ""  PC
 SG_ S_U08_M2P_Cfg5_SBMUs_Num : 8|8@1+ (1,0) [0|255] ""  PC
 SG_ M2P_Cfg5_TnkRunAmnt_27 : 16|8@1+ (1,0) [0|255] ""  PC
 SG_ M2P_Cfg5_ProtocolA_Ver_27 : 24|8@1+ (1,0) [0|255] ""  PC

BO_ 2416373420 M2P_Cfg5__28: 8 MBMU
 SG_ M2P_Cfg5_MBMU_Add_28 : 0|8@1+ (1,0) [0|255] ""  PC
 SG_ S_U08_M2P_Cfg5_SBMUs_Num : 8|8@1+ (1,0) [0|255] ""  PC
 SG_ M2P_Cfg5_TnkRunAmnt_28 : 16|8@1+ (1,0) [0|255] ""  PC
 SG_ M2P_Cfg5_ProtocolA_Ver_28 : 24|8@1+ (1,0) [0|255] ""  PC

BO_ 2416373421 M2P_Cfg5__29: 8 MBMU
 SG_ M2P_Cfg5_MBMU_Add_29 : 0|8@1+ (1,0) [0|255] ""  PC
 SG_ S_U08_M2P_Cfg5_SBMUs_Num : 8|8@1+ (1,0) [0|255] ""  PC
 SG_ M2P_Cfg5_TnkRunAmnt_29 : 16|8@1+ (1,0) [0|255] ""  PC
 SG_ M2P_Cfg5_ProtocolA_Ver_29 : 24|8@1+ (1,0) [0|255] ""  PC

BO_ 2416373422 M2P_Cfg5__30: 8 MBMU
 SG_ M2P_Cfg5_MBMU_Add_30 : 0|8@1+ (1,0) [0|255] ""  PC
 SG_ S_U08_M2P_Cfg5_SBMUs_Num : 8|8@1+ (1,0) [0|255] ""  PC
 SG_ M2P_Cfg5_TnkRunAmnt_30 : 16|8@1+ (1,0) [0|255] ""  PC
 SG_ M2P_Cfg5_ProtocolA_Ver_30 : 24|8@1+ (1,0) [0|255] ""  PC

BO_ 2416373423 M2P_Cfg5__31: 8 MBMU
 SG_ M2P_Cfg5_MBMU_Add_31 : 0|8@1+ (1,0) [0|255] ""  PC
 SG_ S_U08_M2P_Cfg5_SBMUs_Num : 8|8@1+ (1,0) [0|255] ""  PC
 SG_ M2P_Cfg5_TnkRunAmnt_31 : 16|8@1+ (1,0) [0|255] ""  PC
 SG_ M2P_Cfg5_ProtocolA_Ver_31 : 24|8@1+ (1,0) [0|255] ""  PC

BO_ 2416438929 M2P_Lmt1__01: 8 MBMU
 SG_ M2P_Lmt1_Iso_1_01 : 0|16@1+ (1,0) [0|65535] "kohm"  PC
 SG_ M2P_Lmt1_Iso_2_01 : 16|16@1+ (1,0) [0|65535] "kohm"  PC
 SG_ M2P_Lmt1_Iso_3_01 : 32|16@1+ (1,0) [0|65535] "kohm"  PC
 SG_ M2P_Lmt1_BatClusterCurWarn_1_01 : 48|16@1+ (0.01,0) [0|655.35] "A"  PC

BO_ 2416438930 M2P_Lmt1__02: 8 MBMU
 SG_ M2P_Lmt1_Iso_1_02 : 0|16@1+ (1,0) [0|65535] "kohm"  PC
 SG_ M2P_Lmt1_Iso_2_02 : 16|16@1+ (1,0) [0|65535] "kohm"  PC
 SG_ M2P_Lmt1_Iso_3_02 : 32|16@1+ (1,0) [0|65535] "kohm"  PC
 SG_ M2P_Lmt1_BatClusterCurWarn_1_02 : 48|16@1+ (0.01,0) [0|655.35] "A"  PC

BO_ 2416438931 M2P_Lmt1__03: 8 MBMU
 SG_ M2P_Lmt1_Iso_1_03 : 0|16@1+ (1,0) [0|65535] "kohm"  PC
 SG_ M2P_Lmt1_Iso_2_03 : 16|16@1+ (1,0) [0|65535] "kohm"  PC
 SG_ M2P_Lmt1_Iso_3_03 : 32|16@1+ (1,0) [0|65535] "kohm"  PC
 SG_ M2P_Lmt1_BatClusterCurWarn_1_03 : 48|16@1+ (0.01,0) [0|655.35] "A"  PC

BO_ 2416438932 M2P_Lmt1__04: 8 MBMU
 SG_ M2P_Lmt1_Iso_1_04 : 0|16@1+ (1,0) [0|65535] "kohm"  PC
 SG_ M2P_Lmt1_Iso_2_04 : 16|16@1+ (1,0) [0|65535] "kohm"  PC
 SG_ M2P_Lmt1_Iso_3_04 : 32|16@1+ (1,0) [0|65535] "kohm"  PC
 SG_ M2P_Lmt1_BatClusterCurWarn_1_04 : 48|16@1+ (0.01,0) [0|655.35] "A"  PC

BO_ 2416438933 M2P_Lmt1__05: 8 MBMU
 SG_ M2P_Lmt1_Iso_1_05 : 0|16@1+ (1,0) [0|65535] "kohm"  PC
 SG_ M2P_Lmt1_Iso_2_05 : 16|16@1+ (1,0) [0|65535] "kohm"  PC
 SG_ M2P_Lmt1_Iso_3_05 : 32|16@1+ (1,0) [0|65535] "kohm"  PC
 SG_ M2P_Lmt1_BatClusterCurWarn_1_05 : 48|16@1+ (0.01,0) [0|655.35] "A"  PC

BO_ 2416438934 M2P_Lmt1__06: 8 MBMU
 SG_ M2P_Lmt1_Iso_1_06 : 0|16@1+ (1,0) [0|65535] "kohm"  PC
 SG_ M2P_Lmt1_Iso_2_06 : 16|16@1+ (1,0) [0|65535] "kohm"  PC
 SG_ M2P_Lmt1_Iso_3_06 : 32|16@1+ (1,0) [0|65535] "kohm"  PC
 SG_ M2P_Lmt1_BatClusterCurWarn_1_06 : 48|16@1+ (0.01,0) [0|655.35] "A"  PC

BO_ 2416438935 M2P_Lmt1__07: 8 MBMU
 SG_ M2P_Lmt1_Iso_1_07 : 0|16@1+ (1,0) [0|65535] "kohm"  PC
 SG_ M2P_Lmt1_Iso_2_07 : 16|16@1+ (1,0) [0|65535] "kohm"  PC
 SG_ M2P_Lmt1_Iso_3_07 : 32|16@1+ (1,0) [0|65535] "kohm"  PC
 SG_ M2P_Lmt1_BatClusterCurWarn_1_07 : 48|16@1+ (0.01,0) [0|655.35] "A"  PC

BO_ 2416438936 M2P_Lmt1__08: 8 MBMU
 SG_ M2P_Lmt1_Iso_1_08 : 0|16@1+ (1,0) [0|65535] "kohm"  PC
 SG_ M2P_Lmt1_Iso_2_08 : 16|16@1+ (1,0) [0|65535] "kohm"  PC
 SG_ M2P_Lmt1_Iso_3_08 : 32|16@1+ (1,0) [0|65535] "kohm"  PC
 SG_ M2P_Lmt1_BatClusterCurWarn_1_08 : 48|16@1+ (0.01,0) [0|655.35] "A"  PC

BO_ 2416438937 M2P_Lmt1__09: 8 MBMU
 SG_ M2P_Lmt1_Iso_1_09 : 0|16@1+ (1,0) [0|65535] "kohm"  PC
 SG_ M2P_Lmt1_Iso_2_09 : 16|16@1+ (1,0) [0|65535] "kohm"  PC
 SG_ M2P_Lmt1_Iso_3_09 : 32|16@1+ (1,0) [0|65535] "kohm"  PC
 SG_ M2P_Lmt1_BatClusterCurWarn_1_09 : 48|16@1+ (0.01,0) [0|655.35] "A"  PC

BO_ 2416438938 M2P_Lmt1__10: 8 MBMU
 SG_ M2P_Lmt1_Iso_1_10 : 0|16@1+ (1,0) [0|65535] "kohm"  PC
 SG_ M2P_Lmt1_Iso_2_10 : 16|16@1+ (1,0) [0|65535] "kohm"  PC
 SG_ M2P_Lmt1_Iso_3_10 : 32|16@1+ (1,0) [0|65535] "kohm"  PC
 SG_ M2P_Lmt1_BatClusterCurWarn_1_10 : 48|16@1+ (0.01,0) [0|655.35] "A"  PC

BO_ 2416438939 M2P_Lmt1__11: 8 MBMU
 SG_ M2P_Lmt1_Iso_1_11 : 0|16@1+ (1,0) [0|65535] "kohm"  PC
 SG_ M2P_Lmt1_Iso_2_11 : 16|16@1+ (1,0) [0|65535] "kohm"  PC
 SG_ M2P_Lmt1_Iso_3_11 : 32|16@1+ (1,0) [0|65535] "kohm"  PC
 SG_ M2P_Lmt1_BatClusterCurWarn_1_11 : 48|16@1+ (0.01,0) [0|655.35] "A"  PC

BO_ 2416438940 M2P_Lmt1__12: 8 MBMU
 SG_ M2P_Lmt1_Iso_1_12 : 0|16@1+ (1,0) [0|65535] "kohm"  PC
 SG_ M2P_Lmt1_Iso_2_12 : 16|16@1+ (1,0) [0|65535] "kohm"  PC
 SG_ M2P_Lmt1_Iso_3_12 : 32|16@1+ (1,0) [0|65535] "kohm"  PC
 SG_ M2P_Lmt1_BatClusterCurWarn_1_12 : 48|16@1+ (0.01,0) [0|655.35] "A"  PC

BO_ 2416438941 M2P_Lmt1__13: 8 MBMU
 SG_ M2P_Lmt1_Iso_1_13 : 0|16@1+ (1,0) [0|65535] "kohm"  PC
 SG_ M2P_Lmt1_Iso_2_13 : 16|16@1+ (1,0) [0|65535] "kohm"  PC
 SG_ M2P_Lmt1_Iso_3_13 : 32|16@1+ (1,0) [0|65535] "kohm"  PC
 SG_ M2P_Lmt1_BatClusterCurWarn_1_13 : 48|16@1+ (0.01,0) [0|655.35] "A"  PC

BO_ 2416438942 M2P_Lmt1__14: 8 MBMU
 SG_ M2P_Lmt1_Iso_1_14 : 0|16@1+ (1,0) [0|65535] "kohm"  PC
 SG_ M2P_Lmt1_Iso_2_14 : 16|16@1+ (1,0) [0|65535] "kohm"  PC
 SG_ M2P_Lmt1_Iso_3_14 : 32|16@1+ (1,0) [0|65535] "kohm"  PC
 SG_ M2P_Lmt1_BatClusterCurWarn_1_14 : 48|16@1+ (0.01,0) [0|655.35] "A"  PC

BO_ 2416438943 M2P_Lmt1__15: 8 MBMU
 SG_ M2P_Lmt1_Iso_1_15 : 0|16@1+ (1,0) [0|65535] "kohm"  PC
 SG_ M2P_Lmt1_Iso_2_15 : 16|16@1+ (1,0) [0|65535] "kohm"  PC
 SG_ M2P_Lmt1_Iso_3_15 : 32|16@1+ (1,0) [0|65535] "kohm"  PC
 SG_ M2P_Lmt1_BatClusterCurWarn_1_15 : 48|16@1+ (0.01,0) [0|655.35] "A"  PC

BO_ 2416438944 M2P_Lmt1__16: 8 MBMU
 SG_ M2P_Lmt1_Iso_1_16 : 0|16@1+ (1,0) [0|65535] "kohm"  PC
 SG_ M2P_Lmt1_Iso_2_16 : 16|16@1+ (1,0) [0|65535] "kohm"  PC
 SG_ M2P_Lmt1_Iso_3_16 : 32|16@1+ (1,0) [0|65535] "kohm"  PC
 SG_ M2P_Lmt1_BatClusterCurWarn_1_16 : 48|16@1+ (0.01,0) [0|655.35] "A"  PC

BO_ 2416438945 M2P_Lmt1__17: 8 MBMU
 SG_ M2P_Lmt1_Iso_1_17 : 0|16@1+ (1,0) [0|65535] "kohm"  PC
 SG_ M2P_Lmt1_Iso_2_17 : 16|16@1+ (1,0) [0|65535] "kohm"  PC
 SG_ M2P_Lmt1_Iso_3_17 : 32|16@1+ (1,0) [0|65535] "kohm"  PC
 SG_ M2P_Lmt1_BatClusterCurWarn_1_17 : 48|16@1+ (0.01,0) [0|655.35] "A"  PC

BO_ 2416438946 M2P_Lmt1__18: 8 MBMU
 SG_ M2P_Lmt1_Iso_1_18 : 0|16@1+ (1,0) [0|65535] "kohm"  PC
 SG_ M2P_Lmt1_Iso_2_18 : 16|16@1+ (1,0) [0|65535] "kohm"  PC
 SG_ M2P_Lmt1_Iso_3_18 : 32|16@1+ (1,0) [0|65535] "kohm"  PC
 SG_ M2P_Lmt1_BatClusterCurWarn_1_18 : 48|16@1+ (0.01,0) [0|655.35] "A"  PC

BO_ 2416438947 M2P_Lmt1__19: 8 MBMU
 SG_ M2P_Lmt1_Iso_1_19 : 0|16@1+ (1,0) [0|65535] "kohm"  PC
 SG_ M2P_Lmt1_Iso_2_19 : 16|16@1+ (1,0) [0|65535] "kohm"  PC
 SG_ M2P_Lmt1_Iso_3_19 : 32|16@1+ (1,0) [0|65535] "kohm"  PC
 SG_ M2P_Lmt1_BatClusterCurWarn_1_19 : 48|16@1+ (0.01,0) [0|655.35] "A"  PC

BO_ 2416438948 M2P_Lmt1__20: 8 MBMU
 SG_ M2P_Lmt1_Iso_1_20 : 0|16@1+ (1,0) [0|65535] "kohm"  PC
 SG_ M2P_Lmt1_Iso_2_20 : 16|16@1+ (1,0) [0|65535] "kohm"  PC
 SG_ M2P_Lmt1_Iso_3_20 : 32|16@1+ (1,0) [0|65535] "kohm"  PC
 SG_ M2P_Lmt1_BatClusterCurWarn_1_20 : 48|16@1+ (0.01,0) [0|655.35] "A"  PC

BO_ 2416438949 M2P_Lmt1__21: 8 MBMU
 SG_ M2P_Lmt1_Iso_1_21 : 0|16@1+ (1,0) [0|65535] "kohm"  PC
 SG_ M2P_Lmt1_Iso_2_21 : 16|16@1+ (1,0) [0|65535] "kohm"  PC
 SG_ M2P_Lmt1_Iso_3_21 : 32|16@1+ (1,0) [0|65535] "kohm"  PC
 SG_ M2P_Lmt1_BatClusterCurWarn_1_21 : 48|16@1+ (0.01,0) [0|655.35] "A"  PC

BO_ 2416438950 M2P_Lmt1__22: 8 MBMU
 SG_ M2P_Lmt1_Iso_1_22 : 0|16@1+ (1,0) [0|65535] "kohm"  PC
 SG_ M2P_Lmt1_Iso_2_22 : 16|16@1+ (1,0) [0|65535] "kohm"  PC
 SG_ M2P_Lmt1_Iso_3_22 : 32|16@1+ (1,0) [0|65535] "kohm"  PC
 SG_ M2P_Lmt1_BatClusterCurWarn_1_22 : 48|16@1+ (0.01,0) [0|655.35] "A"  PC

BO_ 2416438951 M2P_Lmt1__23: 8 MBMU
 SG_ M2P_Lmt1_Iso_1_23 : 0|16@1+ (1,0) [0|65535] "kohm"  PC
 SG_ M2P_Lmt1_Iso_2_23 : 16|16@1+ (1,0) [0|65535] "kohm"  PC
 SG_ M2P_Lmt1_Iso_3_23 : 32|16@1+ (1,0) [0|65535] "kohm"  PC
 SG_ M2P_Lmt1_BatClusterCurWarn_1_23 : 48|16@1+ (0.01,0) [0|655.35] "A"  PC

BO_ 2416438952 M2P_Lmt1__24: 8 MBMU
 SG_ M2P_Lmt1_Iso_1_24 : 0|16@1+ (1,0) [0|65535] "kohm"  PC
 SG_ M2P_Lmt1_Iso_2_24 : 16|16@1+ (1,0) [0|65535] "kohm"  PC
 SG_ M2P_Lmt1_Iso_3_24 : 32|16@1+ (1,0) [0|65535] "kohm"  PC
 SG_ M2P_Lmt1_BatClusterCurWarn_1_24 : 48|16@1+ (0.01,0) [0|655.35] "A"  PC

BO_ 2416438953 M2P_Lmt1__25: 8 MBMU
 SG_ M2P_Lmt1_Iso_1_25 : 0|16@1+ (1,0) [0|65535] "kohm"  PC
 SG_ M2P_Lmt1_Iso_2_25 : 16|16@1+ (1,0) [0|65535] "kohm"  PC
 SG_ M2P_Lmt1_Iso_3_25 : 32|16@1+ (1,0) [0|65535] "kohm"  PC
 SG_ M2P_Lmt1_BatClusterCurWarn_1_25 : 48|16@1+ (0.01,0) [0|655.35] "A"  PC

BO_ 2416438954 M2P_Lmt1__26: 8 MBMU
 SG_ M2P_Lmt1_Iso_1_26 : 0|16@1+ (1,0) [0|65535] "kohm"  PC
 SG_ M2P_Lmt1_Iso_2_26 : 16|16@1+ (1,0) [0|65535] "kohm"  PC
 SG_ M2P_Lmt1_Iso_3_26 : 32|16@1+ (1,0) [0|65535] "kohm"  PC
 SG_ M2P_Lmt1_BatClusterCurWarn_1_26 : 48|16@1+ (0.01,0) [0|655.35] "A"  PC

BO_ 2416438955 M2P_Lmt1__27: 8 MBMU
 SG_ M2P_Lmt1_Iso_1_27 : 0|16@1+ (1,0) [0|65535] "kohm"  PC
 SG_ M2P_Lmt1_Iso_2_27 : 16|16@1+ (1,0) [0|65535] "kohm"  PC
 SG_ M2P_Lmt1_Iso_3_27 : 32|16@1+ (1,0) [0|65535] "kohm"  PC
 SG_ M2P_Lmt1_BatClusterCurWarn_1_27 : 48|16@1+ (0.01,0) [0|655.35] "A"  PC

BO_ 2416438956 M2P_Lmt1__28: 8 MBMU
 SG_ M2P_Lmt1_Iso_1_28 : 0|16@1+ (1,0) [0|65535] "kohm"  PC
 SG_ M2P_Lmt1_Iso_2_28 : 16|16@1+ (1,0) [0|65535] "kohm"  PC
 SG_ M2P_Lmt1_Iso_3_28 : 32|16@1+ (1,0) [0|65535] "kohm"  PC
 SG_ M2P_Lmt1_BatClusterCurWarn_1_28 : 48|16@1+ (0.01,0) [0|655.35] "A"  PC

BO_ 2416438957 M2P_Lmt1__29: 8 MBMU
 SG_ M2P_Lmt1_Iso_1_29 : 0|16@1+ (1,0) [0|65535] "kohm"  PC
 SG_ M2P_Lmt1_Iso_2_29 : 16|16@1+ (1,0) [0|65535] "kohm"  PC
 SG_ M2P_Lmt1_Iso_3_29 : 32|16@1+ (1,0) [0|65535] "kohm"  PC
 SG_ M2P_Lmt1_BatClusterCurWarn_1_29 : 48|16@1+ (0.01,0) [0|655.35] "A"  PC

BO_ 2416438958 M2P_Lmt1__30: 8 MBMU
 SG_ M2P_Lmt1_Iso_1_30 : 0|16@1+ (1,0) [0|65535] "kohm"  PC
 SG_ M2P_Lmt1_Iso_2_30 : 16|16@1+ (1,0) [0|65535] "kohm"  PC
 SG_ M2P_Lmt1_Iso_3_30 : 32|16@1+ (1,0) [0|65535] "kohm"  PC
 SG_ M2P_Lmt1_BatClusterCurWarn_1_30 : 48|16@1+ (0.01,0) [0|655.35] "A"  PC

BO_ 2416438959 M2P_Lmt1__31: 8 MBMU
 SG_ M2P_Lmt1_Iso_1_31 : 0|16@1+ (1,0) [0|65535] "kohm"  PC
 SG_ M2P_Lmt1_Iso_2_31 : 16|16@1+ (1,0) [0|65535] "kohm"  PC
 SG_ M2P_Lmt1_Iso_3_31 : 32|16@1+ (1,0) [0|65535] "kohm"  PC
 SG_ M2P_Lmt1_BatClusterCurWarn_1_31 : 48|16@1+ (0.01,0) [0|655.35] "A"  PC

BO_ 2416504465 M2P_Lmt2__01: 8 MBMU
 SG_ M2P_Lmt2_BatClusterCurWarn_2_01 : 0|16@1+ (0.01,0) [0|655.35] "A"  PC
 SG_ M2P_Lmt2_BatClusterCurWarn_3_01 : 16|16@1+ (0.01,0) [0|655.35] "A"  PC

BO_ 2416504466 M2P_Lmt2__02: 8 MBMU
 SG_ M2P_Lmt2_BatClusterCurWarn_2_02 : 0|16@1+ (0.01,0) [0|655.35] "A"  PC
 SG_ M2P_Lmt2_BatClusterCurWarn_3_02 : 16|16@1+ (0.01,0) [0|655.35] "A"  PC

BO_ 2416504467 M2P_Lmt2__03: 8 MBMU
 SG_ M2P_Lmt2_BatClusterCurWarn_2_03 : 0|16@1+ (0.01,0) [0|655.35] "A"  PC
 SG_ M2P_Lmt2_BatClusterCurWarn_3_03 : 16|16@1+ (0.01,0) [0|655.35] "A"  PC

BO_ 2416504468 M2P_Lmt2__04: 8 MBMU
 SG_ M2P_Lmt2_BatClusterCurWarn_2_04 : 0|16@1+ (0.01,0) [0|655.35] "A"  PC
 SG_ M2P_Lmt2_BatClusterCurWarn_3_04 : 16|16@1+ (0.01,0) [0|655.35] "A"  PC

BO_ 2416504469 M2P_Lmt2__05: 8 MBMU
 SG_ M2P_Lmt2_BatClusterCurWarn_2_05 : 0|16@1+ (0.01,0) [0|655.35] "A"  PC
 SG_ M2P_Lmt2_BatClusterCurWarn_3_05 : 16|16@1+ (0.01,0) [0|655.35] "A"  PC

BO_ 2416504470 M2P_Lmt2__06: 8 MBMU
 SG_ M2P_Lmt2_BatClusterCurWarn_2_06 : 0|16@1+ (0.01,0) [0|655.35] "A"  PC
 SG_ M2P_Lmt2_BatClusterCurWarn_3_06 : 16|16@1+ (0.01,0) [0|655.35] "A"  PC

BO_ 2416504471 M2P_Lmt2__07: 8 MBMU
 SG_ M2P_Lmt2_BatClusterCurWarn_2_07 : 0|16@1+ (0.01,0) [0|655.35] "A"  PC
 SG_ M2P_Lmt2_BatClusterCurWarn_3_07 : 16|16@1+ (0.01,0) [0|655.35] "A"  PC

BO_ 2416504472 M2P_Lmt2__08: 8 MBMU
 SG_ M2P_Lmt2_BatClusterCurWarn_2_08 : 0|16@1+ (0.01,0) [0|655.35] "A"  PC
 SG_ M2P_Lmt2_BatClusterCurWarn_3_08 : 16|16@1+ (0.01,0) [0|655.35] "A"  PC

BO_ 2416504473 M2P_Lmt2__09: 8 MBMU
 SG_ M2P_Lmt2_BatClusterCurWarn_2_09 : 0|16@1+ (0.01,0) [0|655.35] "A"  PC
 SG_ M2P_Lmt2_BatClusterCurWarn_3_09 : 16|16@1+ (0.01,0) [0|655.35] "A"  PC

BO_ 2416504474 M2P_Lmt2__10: 8 MBMU
 SG_ M2P_Lmt2_BatClusterCurWarn_2_10 : 0|16@1+ (0.01,0) [0|655.35] "A"  PC
 SG_ M2P_Lmt2_BatClusterCurWarn_3_10 : 16|16@1+ (0.01,0) [0|655.35] "A"  PC

BO_ 2416504475 M2P_Lmt2__11: 8 MBMU
 SG_ M2P_Lmt2_BatClusterCurWarn_2_11 : 0|16@1+ (0.01,0) [0|655.35] "A"  PC
 SG_ M2P_Lmt2_BatClusterCurWarn_3_11 : 16|16@1+ (0.01,0) [0|655.35] "A"  PC

BO_ 2416504476 M2P_Lmt2__12: 8 MBMU
 SG_ M2P_Lmt2_BatClusterCurWarn_2_12 : 0|16@1+ (0.01,0) [0|655.35] "A"  PC
 SG_ M2P_Lmt2_BatClusterCurWarn_3_12 : 16|16@1+ (0.01,0) [0|655.35] "A"  PC

BO_ 2416504477 M2P_Lmt2__13: 8 MBMU
 SG_ M2P_Lmt2_BatClusterCurWarn_2_13 : 0|16@1+ (0.01,0) [0|655.35] "A"  PC
 SG_ M2P_Lmt2_BatClusterCurWarn_3_13 : 16|16@1+ (0.01,0) [0|655.35] "A"  PC

BO_ 2416504478 M2P_Lmt2__14: 8 MBMU
 SG_ M2P_Lmt2_BatClusterCurWarn_2_14 : 0|16@1+ (0.01,0) [0|655.35] "A"  PC
 SG_ M2P_Lmt2_BatClusterCurWarn_3_14 : 16|16@1+ (0.01,0) [0|655.35] "A"  PC

BO_ 2416504479 M2P_Lmt2__15: 8 MBMU
 SG_ M2P_Lmt2_BatClusterCurWarn_2_15 : 0|16@1+ (0.01,0) [0|655.35] "A"  PC
 SG_ M2P_Lmt2_BatClusterCurWarn_3_15 : 16|16@1+ (0.01,0) [0|655.35] "A"  PC

BO_ 2416504480 M2P_Lmt2__16: 8 MBMU
 SG_ M2P_Lmt2_BatClusterCurWarn_2_16 : 0|16@1+ (0.01,0) [0|655.35] "A"  PC
 SG_ M2P_Lmt2_BatClusterCurWarn_3_16 : 16|16@1+ (0.01,0) [0|655.35] "A"  PC

BO_ 2416504481 M2P_Lmt2__17: 8 MBMU
 SG_ M2P_Lmt2_BatClusterCurWarn_2_17 : 0|16@1+ (0.01,0) [0|655.35] "A"  PC
 SG_ M2P_Lmt2_BatClusterCurWarn_3_17 : 16|16@1+ (0.01,0) [0|655.35] "A"  PC

BO_ 2416504482 M2P_Lmt2__18: 8 MBMU
 SG_ M2P_Lmt2_BatClusterCurWarn_2_18 : 0|16@1+ (0.01,0) [0|655.35] "A"  PC
 SG_ M2P_Lmt2_BatClusterCurWarn_3_18 : 16|16@1+ (0.01,0) [0|655.35] "A"  PC

BO_ 2416504483 M2P_Lmt2__19: 8 MBMU
 SG_ M2P_Lmt2_BatClusterCurWarn_2_19 : 0|16@1+ (0.01,0) [0|655.35] "A"  PC
 SG_ M2P_Lmt2_BatClusterCurWarn_3_19 : 16|16@1+ (0.01,0) [0|655.35] "A"  PC

BO_ 2416504484 M2P_Lmt2__20: 8 MBMU
 SG_ M2P_Lmt2_BatClusterCurWarn_2_20 : 0|16@1+ (0.01,0) [0|655.35] "A"  PC
 SG_ M2P_Lmt2_BatClusterCurWarn_3_20 : 16|16@1+ (0.01,0) [0|655.35] "A"  PC

BO_ 2416504485 M2P_Lmt2__21: 8 MBMU
 SG_ M2P_Lmt2_BatClusterCurWarn_2_21 : 0|16@1+ (0.01,0) [0|655.35] "A"  PC
 SG_ M2P_Lmt2_BatClusterCurWarn_3_21 : 16|16@1+ (0.01,0) [0|655.35] "A"  PC

BO_ 2416504486 M2P_Lmt2__22: 8 MBMU
 SG_ M2P_Lmt2_BatClusterCurWarn_2_22 : 0|16@1+ (0.01,0) [0|655.35] "A"  PC
 SG_ M2P_Lmt2_BatClusterCurWarn_3_22 : 16|16@1+ (0.01,0) [0|655.35] "A"  PC

BO_ 2416504487 M2P_Lmt2__23: 8 MBMU
 SG_ M2P_Lmt2_BatClusterCurWarn_2_23 : 0|16@1+ (0.01,0) [0|655.35] "A"  PC
 SG_ M2P_Lmt2_BatClusterCurWarn_3_23 : 16|16@1+ (0.01,0) [0|655.35] "A"  PC

BO_ 2416504488 M2P_Lmt2__24: 8 MBMU
 SG_ M2P_Lmt2_BatClusterCurWarn_2_24 : 0|16@1+ (0.01,0) [0|655.35] "A"  PC
 SG_ M2P_Lmt2_BatClusterCurWarn_3_24 : 16|16@1+ (0.01,0) [0|655.35] "A"  PC

BO_ 2416504489 M2P_Lmt2__25: 8 MBMU
 SG_ M2P_Lmt2_BatClusterCurWarn_2_25 : 0|16@1+ (0.01,0) [0|655.35] "A"  PC
 SG_ M2P_Lmt2_BatClusterCurWarn_3_25 : 16|16@1+ (0.01,0) [0|655.35] "A"  PC

BO_ 2416504490 M2P_Lmt2__26: 8 MBMU
 SG_ M2P_Lmt2_BatClusterCurWarn_2_26 : 0|16@1+ (0.01,0) [0|655.35] "A"  PC
 SG_ M2P_Lmt2_BatClusterCurWarn_3_26 : 16|16@1+ (0.01,0) [0|655.35] "A"  PC

BO_ 2416504491 M2P_Lmt2__27: 8 MBMU
 SG_ M2P_Lmt2_BatClusterCurWarn_2_27 : 0|16@1+ (0.01,0) [0|655.35] "A"  PC
 SG_ M2P_Lmt2_BatClusterCurWarn_3_27 : 16|16@1+ (0.01,0) [0|655.35] "A"  PC

BO_ 2416504492 M2P_Lmt2__28: 8 MBMU
 SG_ M2P_Lmt2_BatClusterCurWarn_2_28 : 0|16@1+ (0.01,0) [0|655.35] "A"  PC
 SG_ M2P_Lmt2_BatClusterCurWarn_3_28 : 16|16@1+ (0.01,0) [0|655.35] "A"  PC

BO_ 2416504493 M2P_Lmt2__29: 8 MBMU
 SG_ M2P_Lmt2_BatClusterCurWarn_2_29 : 0|16@1+ (0.01,0) [0|655.35] "A"  PC
 SG_ M2P_Lmt2_BatClusterCurWarn_3_29 : 16|16@1+ (0.01,0) [0|655.35] "A"  PC

BO_ 2416504494 M2P_Lmt2__30: 8 MBMU
 SG_ M2P_Lmt2_BatClusterCurWarn_2_30 : 0|16@1+ (0.01,0) [0|655.35] "A"  PC
 SG_ M2P_Lmt2_BatClusterCurWarn_3_30 : 16|16@1+ (0.01,0) [0|655.35] "A"  PC

BO_ 2416504495 M2P_Lmt2__31: 8 MBMU
 SG_ M2P_Lmt2_BatClusterCurWarn_2_31 : 0|16@1+ (0.01,0) [0|655.35] "A"  PC
 SG_ M2P_Lmt2_BatClusterCurWarn_3_31 : 16|16@1+ (0.01,0) [0|655.35] "A"  PC

BO_ 2164391918 P2A_LIFE: 8 PC
 SG_ CRC_P2A : 0|8@1+ (1,0) [0|255] ""  SBMU,MBMU
 SG_ ALIV_P2A : 8|4@1+ (1,0) [0|15] ""  SBMU,MBMU

BO_ 2165506030 P2A_RTC: 8 PC
 SG_ CRC_P2A_RTC : 0|8@1+ (1,0) [0|255] ""  SBMU,MBMU
 SG_ RTC_Year : 8|8@1+ (1,2000) [0|2255] ""  SBMU,MBMU
 SG_ RTC_Month : 16|8@1+ (1,0) [0|255] ""  SBMU,MBMU
 SG_ RTC_date : 24|8@1+ (1,0) [0|255] ""  SBMU,MBMU
 SG_ RTC_Hour : 32|8@1+ (1,0) [0|255] ""  SBMU,MBMU
 SG_ RTC_minute : 40|8@1+ (1,0) [0|255] ""  SBMU,MBMU
 SG_ RTC_second : 48|8@1+ (1,0) [0|255] ""  SBMU,MBMU
 SG_ RTC_CMD : 56|8@1+ (1,0) [0|255] ""  SBMU,MBMU

BO_ 2165407726 P2S_CMD: 8 PC
 SG_ CRC_P2S_CMD : 0|8@1+ (1,0) [0|255] ""  SBMU
 SG_ P2S_SBMU_No : 8|8@1+ (1,0) [0|255] ""  SBMU
 SG_ RQ_Read_Detail_Data : 16|2@1+ (1,0) [0|3] ""  SBMU
 SG_ P2S_CMD_Data0 : 18|6@1+ (1,0) [0|63] ""  SBMU
 SG_ P2S_CMD_Data1 : 24|8@1+ (1,0) [0|255] ""  SBMU
 SG_ P2S_CMD_Data2 : 32|8@1+ (1,0) [0|255] ""  SBMU
 SG_ P2S_CMD_Data3 : 40|8@1+ (1,0) [0|255] ""  SBMU
 SG_ P2S_CMD_Data4 : 48|8@1+ (1,0) [0|255] ""  SBMU
 SG_ P2S_CMD_Data5 : 56|8@1+ (1,0) [0|255] ""  SBMU

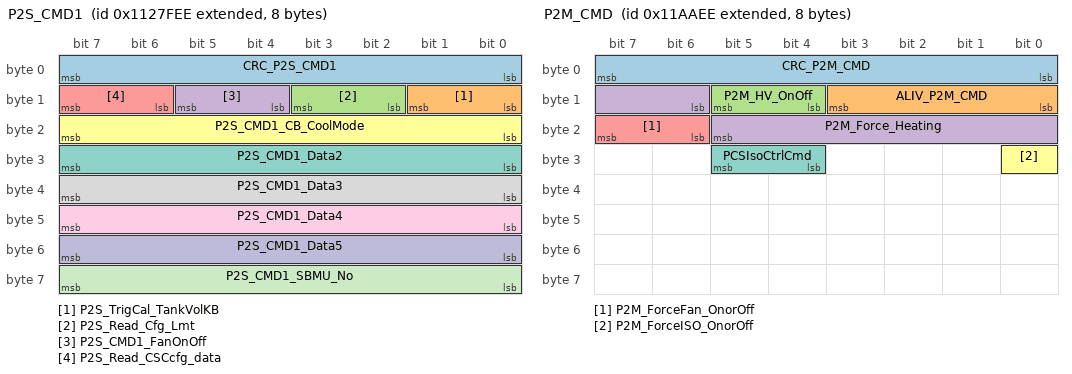
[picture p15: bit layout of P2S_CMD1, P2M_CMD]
BO_ 2165473262 P2S_CMD1: 8 PC
 SG_ CRC_P2S_CMD1 : 0|8@1+ (1,0) [0|255] ""  SBMU
 SG_ P2S_TrigCal_TankVolKB : 8|2@1+ (1,0) [0|3] ""  SBMU
 SG_ P2S_Read_Cfg_Lmt : 10|2@1+ (1,0) [0|3] ""  SBMU
 SG_ P2S_CMD1_FanOnOff : 12|2@1+ (1,0) [0|3] ""  SBMU
 SG_ P2S_Read_CSCcfg_data : 14|2@1+ (1,0) [0|3] ""  SBMU
 SG_ P2S_CMD1_CB_CoolMode : 16|8@1+ (1,0) [0|255] ""  SBMU
 SG_ P2S_CMD1_Data2 : 24|8@1+ (1,0) [0|255] ""  SBMU
 SG_ P2S_CMD1_Data3 : 32|8@1+ (1,0) [0|255] ""  SBMU
 SG_ P2S_CMD1_Data4 : 40|8@1+ (1,0) [0|255] ""  SBMU
 SG_ P2S_CMD1_Data5 : 48|8@1+ (1,0) [0|255] ""  SBMU
 SG_ P2S_CMD1_SBMU_No : 56|8@1+ (1,0) [0|255] ""  SBMU

BO_ 2433908718 P2S_Index: 8 PC
 SG_ P2S_Index_CRC : 0|8@1+ (1,0) [0|255] ""  SBMU
 SG_ P2S_Index_Enable : 8|8@1+ (1,0) [0|255] ""  SBMU
 SG_ P2S_Index_Data0 : 16|8@1+ (1,0) [0|255] ""  SBMU
 SG_ P2S_Index_Data1 : 24|8@1+ (1,0) [0|255] ""  SBMU
 SG_ P2S_Index_Data2 : 32|8@1+ (1,0) [0|255] ""  SBMU
 SG_ P2S_Index_Data3 : 40|8@1+ (1,0) [0|255] ""  SBMU
 SG_ P2S_Index_Data4 : 48|8@1+ (1,0) [0|255] ""  SBMU
 SG_ P2S_Index_Data5 : 56|8@1+ (1,0) [0|255] ""  SBMU

BO_ 2432794606 P2S_DIAG: 8 PC
 SG_ P2S_DIAG_BYTE1 : 0|8@1+ (1,0) [0|255] ""  SBMU
 SG_ P2S_DIAG_BYTE2 : 8|8@1+ (1,0) [0|255] ""  SBMU
 SG_ P2S_DIAG_BYTE3 : 16|8@1+ (1,0) [0|255] ""  SBMU
 SG_ P2S_DIAG_BYTE4 : 24|8@1+ (1,0) [0|255] ""  SBMU
 SG_ P2S_DIAG_BYTE5 : 32|8@1+ (1,0) [0|255] ""  SBMU
 SG_ P2S_DIAG_BYTE6 : 40|8@1+ (1,0) [0|255] ""  SBMU
 SG_ P2S_DIAG_BYTE7 : 48|8@1+ (1,0) [0|255] ""  SBMU
 SG_ P2S_DIAG_BYTE8 : 56|8@1+ (1,0) [0|255] ""  SBMU

BO_ 2433122286 P2MSD_Cfg: 8 PC
 SG_ P2MSD_Cfg : 0|8@1+ (1,0) [0|255] ""  SBMU
 SG_ P2MSD_Cfg_Addr : 8|8@1+ (1,0) [0|255] ""  SBMU
 SG_ P2MSD_Cfg_Data1 : 16|8@1+ (1,0) [0|255] ""  SBMU
 SG_ P2MSD_Cfg_Data2 : 24|8@1+ (1,0) [0|255] ""  SBMU
 SG_ P2MSD_Cfg_Data3 : 32|8@1+ (1,0) [0|255] ""  SBMU
 SG_ P2MSD_Cfg_Data4 : 40|8@1+ (1,0) [0|255] ""  SBMU
 SG_ P2MSD_Cfg_Data5 : 48|8@1+ (1,0) [0|255] ""  SBMU
 SG_ P2MSD_Cfg_Data6 : 56|8@1+ (1,0) [0|255] ""  SBMU

BO_ 2163802095 P2S_Boot1: 8 PC
 SG_ P2S_Boot1_Data0 : 0|8@1+ (1,0) [0|255] ""  SBMU,IMM
 SG_ P2S_Boot1_Data1 : 8|8@1+ (1,0) [0|255] ""  SBMU,IMM
 SG_ P2S_Boot1_Data2 : 16|8@1+ (1,0) [0|255] ""  SBMU,IMM
 SG_ P2S_Boot1_Data3 : 24|8@1+ (1,0) [0|255] ""  SBMU,IMM
 SG_ P2S_Boot1_Data4 : 32|8@1+ (1,0) [0|255] ""  SBMU,IMM
 SG_ P2S_Boot1_Data5 : 40|8@1+ (1,0) [0|255] ""  SBMU,IMM
 SG_ P2S_Boot1_Data6 : 48|8@1+ (1,0) [0|255] ""  SBMU,IMM
 SG_ P2S_Boot1_Data7 : 56|8@1+ (1,0) [0|255] ""  SBMU,IMM

BO_ 2197356527 P2S_Boot2: 8 PC
 SG_ P2S_Boot2_Data0 : 0|8@1+ (1,0) [0|255] ""  SBMU,IMM
 SG_ P2S_Boot2_Data1 : 8|8@1+ (1,0) [0|255] ""  SBMU,IMM
 SG_ P2S_Boot2_Data2 : 16|8@1+ (1,0) [0|255] ""  SBMU,IMM
 SG_ P2S_Boot2_Data3 : 24|8@1+ (1,0) [0|255] ""  SBMU,IMM
 SG_ P2S_Boot2_Data4 : 32|8@1+ (1,0) [0|255] ""  SBMU,IMM
 SG_ P2S_Boot2_Data5 : 40|8@1+ (1,0) [0|255] ""  SBMU,IMM
 SG_ P2S_Boot2_Data6 : 48|8@1+ (1,0) [0|255] ""  SBMU,IMM
 SG_ P2S_Boot2_Data7 : 56|8@1+ (1,0) [0|255] ""  SBMU,IMM

BO_ 2163933167 P2S_PrgInfo: 8 PC
 SG_ P2S_PrgInfo_Data0 : 0|8@1+ (1,0) [0|255] ""  SBMU
 SG_ P2S_PrgInfo_Data1 : 8|8@1+ (1,0) [0|255] ""  SBMU
 SG_ P2S_PrgInfo_Data2 : 16|8@1+ (1,0) [0|255] ""  SBMU
 SG_ P2S_PrgInfo_Data3 : 24|8@1+ (1,0) [0|255] ""  SBMU
 SG_ P2S_PrgInfo_Data4 : 32|8@1+ (1,0) [0|255] ""  SBMU
 SG_ P2S_PrgInfo_Data5 : 40|8@1+ (1,0) [0|255] ""  SBMU
 SG_ P2S_PrgInfo_Data6 : 48|8@1+ (1,0) [0|255] ""  SBMU
 SG_ P2S_PrgInfo_Data7 : 56|8@1+ (1,0) [0|255] ""  SBMU

BO_ 2163998703 P2S_DLoadInfo: 8 PC
 SG_ P2S_DLoadInfo_Data0 : 0|8@1+ (1,0) [0|255] ""  SBMU
 SG_ P2S_DLoadInfo_Data1 : 8|8@1+ (1,0) [0|255] ""  SBMU
 SG_ P2S_DLoadInfo_Data2 : 16|8@1+ (1,0) [0|255] ""  SBMU
 SG_ P2S_DLoadInfo_Data3 : 24|8@1+ (1,0) [0|255] ""  SBMU
 SG_ P2S_DLoadInfo_Data4 : 32|8@1+ (1,0) [0|255] ""  SBMU
 SG_ P2S_DLoadInfo_Data5 : 40|8@1+ (1,0) [0|255] ""  SBMU
 SG_ P2S_DLoadInfo_Data6 : 48|8@1+ (1,0) [0|255] ""  SBMU
 SG_ P2S_DLoadInfo_Data7 : 56|8@1+ (1,0) [0|255] ""  SBMU

BO_ 2164064239 P2S_PrgData: 8 PC
 SG_ P2S_PrgData_Data0 : 0|8@1+ (1,0) [0|255] ""  SBMU
 SG_ P2S_PrgData_Data1 : 8|8@1+ (1,0) [0|255] ""  SBMU
 SG_ P2S_PrgData_Data2 : 16|8@1+ (1,0) [0|255] ""  SBMU
 SG_ P2S_PrgData_Data3 : 24|8@1+ (1,0) [0|255] ""  SBMU
 SG_ P2S_PrgData_Data4 : 32|8@1+ (1,0) [0|255] ""  SBMU
 SG_ P2S_PrgData_Data5 : 40|8@1+ (1,0) [0|255] ""  SBMU
 SG_ P2S_PrgData_Data6 : 48|8@1+ (1,0) [0|255] ""  SBMU
 SG_ P2S_PrgData_Data7 : 56|8@1+ (1,0) [0|255] ""  SBMU

BO_ 2449342447 P2S_CSCVersion: 8 PC
 SG_ P2S_CSCVer_Data0 : 0|8@1+ (1,0) [0|255] ""  SBMU
 SG_ P2S_CSCVer_Data1 : 8|8@1+ (1,0) [0|255] ""  SBMU
 SG_ P2S_CSCVer_Data2 : 16|8@1+ (1,0) [0|255] ""  SBMU
 SG_ P2S_CSCVer_Data3 : 24|8@1+ (1,0) [0|255] ""  SBMU
 SG_ P2S_CSCVer_Data4 : 32|8@1+ (1,0) [0|255] ""  SBMU
 SG_ P2S_CSCVer_Data5 : 40|8@1+ (1,0) [0|255] ""  SBMU
 SG_ P2S_CSCVer_Data6 : 48|8@1+ (1,0) [0|255] ""  SBMU
 SG_ P2S_CSCVer_Data7 : 56|8@1+ (1,0) [0|255] ""  SBMU

BO_ 2164129775 P2S_BootGetVer: 8 PC
 SG_ P2S_CSCVer_Data0 : 0|8@1+ (1,0) [0|255] ""  SBMU
 SG_ P2S_CSCVer_Data1 : 8|8@1+ (1,0) [0|255] ""  SBMU
 SG_ P2S_CSCVer_Data2 : 16|8@1+ (1,0) [0|255] ""  SBMU
 SG_ P2S_CSCVer_Data3 : 24|8@1+ (1,0) [0|255] ""  SBMU
 SG_ P2S_CSCVer_Data4 : 32|8@1+ (1,0) [0|255] ""  SBMU
 SG_ P2S_CSCVer_Data5 : 40|8@1+ (1,0) [0|255] ""  SBMU
 SG_ P2S_CSCVer_Data6 : 48|8@1+ (1,0) [0|255] ""  SBMU
 SG_ P2S_CSCVer_Data7 : 56|8@1+ (1,0) [0|255] ""  SBMU

BO_ 2432805614 P2M_DIAG: 8 PC
 SG_ P2M_DIAG_BYTE1 : 0|8@1+ (1,0) [0|255] ""  MBMU
 SG_ P2M_DIAG_BYTE2 : 8|8@1+ (1,0) [0|255] ""  MBMU
 SG_ P2M_DIAG_BYTE3 : 16|8@1+ (1,0) [0|255] ""  MBMU
 SG_ P2M_DIAG_BYTE4 : 24|8@1+ (1,0) [0|255] ""  MBMU
 SG_ P2M_DIAG_BYTE5 : 32|8@1+ (1,0) [0|255] ""  MBMU
 SG_ P2M_DIAG_BYTE6 : 40|8@1+ (1,0) [0|255] ""  MBMU
 SG_ P2M_DIAG_BYTE7 : 48|8@1+ (1,0) [0|255] ""  MBMU
 SG_ P2M_DIAG_BYTE8 : 56|8@1+ (1,0) [0|255] ""  MBMU

BO_ 2433133294 P2M_Cfg5: 8 PC
 SG_ P2M_Cfg5_MBMU_CMD : 0|8@1+ (1,0) [0|255] ""  MBMU
 SG_ P2M_Cfg5_MBMU_Add : 8|8@1+ (1,0) [0|255] ""  MBMU
 SG_ P2E_Cfg5_MBMU_data1 : 16|8@1+ (1,0) [0|255] ""  MBMU
 SG_ P2E_Cfg5_MBMU_data2 : 24|8@1+ (1,0) [0|255] ""  MBMU
 SG_ P2E_Cfg5_MBMU_data3 : 32|8@1+ (1,0) [0|255] ""  MBMU
 SG_ P2E_Cfg5_MBMU_data4 : 40|8@1+ (1,0) [0|255] ""  MBMU
 SG_ P2E_Cfg5_MBMU_data5 : 48|8@1+ (1,0) [0|255] ""  MBMU
 SG_ P2E_Cfg5_MBMU_data6 : 56|8@1+ (1,0) [0|255] ""  MBMU

BO_ 2148641518 P2M_CMD: 8 PC
 SG_ CRC_P2M_CMD : 0|8@1+ (1,0) [0|255] ""  MBMU
 SG_ ALIV_P2M_CMD : 8|4@1+ (1,0) [0|15] ""  MBMU
 SG_ P2M_HV_OnOff : 12|2@1+ (1,0) [0|3] ""  MBMU
 SG_ P2M_Force_Heating : 14|8@1+ (1,0) [0|255] ""  MBMU
 SG_ P2M_ForceFan_OnorOff : 22|2@1+ (1,0) [0|3] ""  MBMU
 SG_ P2M_ForceISO_OnorOff : 24|1@1+ (1,0) [0|1] ""  MBMU
 SG_ PCSIsoCtrlCmd : 28|2@1+ (1,0) [0|3] ""  MBMU

BO_ 2148707054 P2M_CMD1: 8 PC
 SG_ P2M_Read_Cfg_Lmt : 0|2@1+ (1,0) [0|3] ""  MBMU
 SG_ Relay_Cmd : 2|2@1+ (1,0) [0|3] ""  MBMU
 SG_ Fault_Clean_Cmd : 4|2@1+ (1,0) [0|3] ""  MBMU
 SG_ PCS_alive_counter : 16|8@1+ (1,0) [0|255] ""  MBMU
 SG_ Reserved1 : 24|48@1+ (1,0) [0|281474976710655] ""  MBMU

BO_ 2332164073 M2I_SUMDATA1: 8 MBMU
 SG_ CRC_M2I_S1 : 0|8@1+ (1,0) [0|255] ""  IMM
 SG_ M2I_S1_HVS : 8|16@1+ (0.1,0) [0|6553.5] "v"  IMM
 SG_ M2I_S1_Enable : 24|2@1+ (1,0) [0|3] ""  IMM
 SG_ M2I_S1_Read_Ver_Enable : 26|2@1+ (1,0) [0|3] ""  IMM
 SG_ M2I_S1_Iso_PostTime : 32|8@1+ (0.01,0) [0|2.55] "s"  IMM
 SG_ M2I_S1_SysABStableTime : 40|16@1+ (0.01,0) [0|655.35] "s"  IMM

BO_ 2332164074 I2A_Info1: 8 IMM
 SG_ I2A_Info1_SW_Ver_Byte1 : 0|8@1+ (1,0) [0|255] ""  MBMU
 SG_ I2A_Info1_SW_Ver_Byte2 : 8|8@1+ (1,0) [0|255] ""  MBMU
 SG_ I2A_Info1_SW_Ver_Byte3 : 16|8@1+ (1,0) [0|255] ""  MBMU
 SG_ I2A_Info1_SW_Ver_Byte4 : 24|8@1+ (1,0) [0|255] ""  MBMU
 SG_ I2A_Info1_SW_Ver_Byte5 : 32|8@1+ (1,0) [0|255] ""  MBMU
 SG_ I2A_Info1_SW_Ver_Byte6 : 40|8@1+ (1,0) [0|255] ""  MBMU
 SG_ I2A_Info1_SW_Ver_Byte7 : 48|8@1+ (1,0) [0|255] ""  MBMU
 SG_ I2A_Info1_SW_Ver_Byte8 : 56|8@1+ (1,0) [0|255] ""  MBMU

BO_ 2332164075 I2A_Info2: 8 IMM
 SG_ I2A_Info2_SW_Ver_Byte9 : 0|8@1+ (1,0) [0|255] ""  MBMU
 SG_ I2A_Info2_SW_Ver_Byte10 : 8|8@1+ (1,0) [0|255] ""  MBMU
 SG_ I2A_Info2_SW_Ver_Byte11 : 16|8@1+ (1,0) [0|255] ""  MBMU
 SG_ I2A_Info2_SW_Ver_Byte12 : 24|8@1+ (1,0) [0|255] ""  MBMU
 SG_ I2A_Info2_SW_Ver_Byte13 : 32|8@1+ (1,0) [0|255] ""  MBMU
 SG_ I2A_Info2_SW_Ver_Byte14 : 40|8@1+ (1,0) [0|255] ""  MBMU
 SG_ I2A_Info2_SW_Ver_Byte15 : 48|8@1+ (1,0) [0|255] ""  MBMU
 SG_ I2A_Info2_SW_Ver_Byte16 : 56|8@1+ (1,0) [0|255] ""  MBMU

BO_ 2332164076 I2A_Info3: 8 IMM
 SG_ I2A_Info3_HW_Ver_Byte1 : 0|8@1+ (1,0) [0|255] ""  MBMU
 SG_ I2A_Info3_HW_Ver_Byte2 : 8|8@1+ (1,0) [0|255] ""  MBMU
 SG_ I2A_Info3_HW_Ver_Byte3 : 16|8@1+ (1,0) [0|255] ""  MBMU
 SG_ I2A_Info3_HW_Ver_Byte4 : 24|8@1+ (1,0) [0|255] ""  MBMU
 SG_ I2A_Info3_HW_Ver_Byte5 : 32|8@1+ (1,0) [0|255] ""  MBMU
 SG_ I2A_Info3_HW_Ver_Byte6 : 40|8@1+ (1,0) [0|255] ""  MBMU
 SG_ I2A_Info3_HW_Ver_Byte7 : 48|8@1+ (1,0) [0|255] ""  MBMU
 SG_ I2A_Info3_HW_Ver_Byte8 : 56|8@1+ (1,0) [0|255] ""  MBMU

BO_ 2332164077 I2A_Info4: 8 IMM
 SG_ I2A_Info4_HW_Ver_Byte9 : 0|8@1+ (1,0) [0|255] ""  MBMU
 SG_ I2A_Info4_HW_Ver_Byte10 : 8|8@1+ (1,0) [0|255] ""  MBMU
 SG_ I2A_Info4_HW_Ver_Byte11 : 16|8@1+ (1,0) [0|255] ""  MBMU
 SG_ I2A_Info4_HW_Ver_Byte12 : 24|8@1+ (1,0) [0|255] ""  MBMU
 SG_ I2A_Info4_HW_Ver_Byte13 : 32|8@1+ (1,0) [0|255] ""  MBMU
 SG_ I2A_Info4_HW_Ver_Byte14 : 40|8@1+ (1,0) [0|255] ""  MBMU
 SG_ I2A_Info4_HW_Ver_Byte15 : 48|8@1+ (1,0) [0|255] ""  MBMU
 SG_ I2A_Info4_HW_Ver_Byte16 : 56|8@1+ (1,0) [0|255] ""  MBMU

BO_ 2332164078 I2A_Info5: 8 IMM
 SG_ I2A_Barcode1 : 0|8@1+ (1,0) [0|255] ""  MBMU
 SG_ I2A_Barcode2 : 8|8@1+ (1,0) [0|255] ""  MBMU
 SG_ I2A_Barcode3 : 16|8@1+ (1,0) [0|255] ""  MBMU
 SG_ I2A_Barcode4 : 24|8@1+ (1,0) [0|255] ""  MBMU
 SG_ I2A_Barcode5 : 32|8@1+ (1,0) [0|255] ""  MBMU
 SG_ I2A_Barcode6 : 40|8@1+ (1,0) [0|255] ""  MBMU

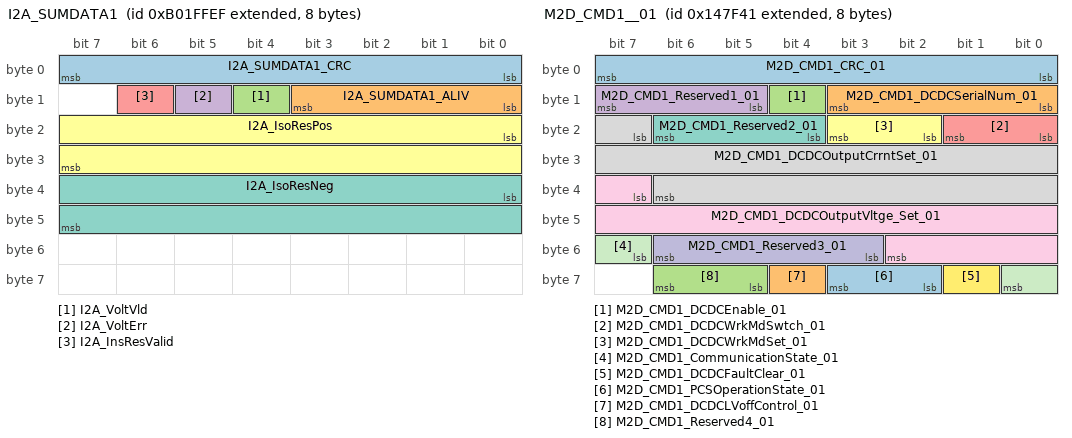
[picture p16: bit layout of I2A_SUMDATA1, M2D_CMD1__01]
BO_ 2332164079 I2A_SUMDATA1: 8 IMM
 SG_ I2A_SUMDATA1_CRC : 0|8@1+ (1,0) [0|255] ""  MBMU,PC
 SG_ I2A_SUMDATA1_ALIV : 8|4@1+ (1,0) [0|15] ""  MBMU,PC
 SG_ I2A_VoltVld : 12|1@1+ (1,0) [0|1] ""  MBMU,PC
 SG_ I2A_VoltErr : 13|1@1+ (1,0) [0|1] ""  MBMU,PC
 SG_ I2A_InsResValid : 14|1@1+ (1,0) [0|1] ""  MBMU,PC
 SG_ I2A_IsoResPos : 16|16@1+ (1,0) [0|65535] "KΩ"  MBMU,PC
 SG_ I2A_IsoResNeg : 32|16@1+ (1,0) [0|65535] "KΩ"  MBMU,PC

BO_ 2148772590 P2M_CMD2: 8 PC

BO_ 2148838126 P2M_CMD3: 8 PC

BO_ 2148903662 P2M_CMD4: 8 PC

BO_ 2148969198 P2M_CMD5: 8 PC

BO_ 2483137262 P2E_Cfg5: 8 PC
 SG_ P2E_Cfg5_MBMU_CMD : 0|8@1+ (1,0) [0|255] ""  ETH
 SG_ P2E_Cfg5_MBMU_Add : 8|8@1+ (1,0) [0|255] ""  ETH
 SG_ P2E_Cfg5_MBMU_data1 : 16|8@1+ (1,0) [0|255] ""  ETH
 SG_ P2E_Cfg5_MBMU_data2 : 24|8@1+ (1,0) [0|255] ""  ETH
 SG_ P2E_Cfg5_MBMU_data3 : 32|8@1+ (1,0) [0|255] ""  ETH
 SG_ P2E_Cfg5_MBMU_data4 : 40|8@1+ (1,0) [0|255] ""  ETH
 SG_ P2E_Cfg5_MBMU_data5 : 48|8@1+ (1,0) [0|255] ""  ETH
 SG_ P2E_Cfg5_MBMU_data6 : 56|8@1+ (1,0) [0|255] ""  ETH

BO_ 2483220113 E2P_SUMDATA1__01: 8 ETH
 SG_ E2P_SUMDATA1_Byte1_01 : 0|8@1+ (1,0) [0|255] ""  MBMU,PC
 SG_ E2P_SUMDATA1_Byte2_01 : 8|8@1+ (1,0) [0|255] ""  MBMU,PC
 SG_ E2P_SUMDATA1_Byte3_01 : 16|16@1+ (1,0) [0|65535] ""  MBMU,PC
 SG_ E2P_SUMDATA1_Byte4_01 : 32|32@1+ (1,0) [0|4294967295] ""  MBMU,PC

BO_ 2483220114 E2P_SUMDATA1__02: 8 ETH
 SG_ E2P_SUMDATA1_Byte1_02 : 0|8@1+ (1,0) [0|255] ""  MBMU,PC
 SG_ E2P_SUMDATA1_Byte2_02 : 8|8@1+ (1,0) [0|255] ""  MBMU,PC
 SG_ E2P_SUMDATA1_Byte3_02 : 16|16@1+ (1,0) [0|65535] ""  MBMU,PC
 SG_ E2P_SUMDATA1_Byte4_02 : 32|32@1+ (1,0) [0|4294967295] ""  MBMU,PC

BO_ 2483220115 E2P_SUMDATA1__03: 8 ETH
 SG_ E2P_SUMDATA1_Byte1_03 : 0|8@1+ (1,0) [0|255] ""  MBMU,PC
 SG_ E2P_SUMDATA1_Byte2_03 : 8|8@1+ (1,0) [0|255] ""  MBMU,PC
 SG_ E2P_SUMDATA1_Byte3_03 : 16|16@1+ (1,0) [0|65535] ""  MBMU,PC
 SG_ E2P_SUMDATA1_Byte4_03 : 32|32@1+ (1,0) [0|4294967295] ""  MBMU,PC

BO_ 2483220116 E2P_SUMDATA1__04: 8 ETH
 SG_ E2P_SUMDATA1_Byte1_04 : 0|8@1+ (1,0) [0|255] ""  MBMU,PC
 SG_ E2P_SUMDATA1_Byte2_04 : 8|8@1+ (1,0) [0|255] ""  MBMU,PC
 SG_ E2P_SUMDATA1_Byte3_04 : 16|16@1+ (1,0) [0|65535] ""  MBMU,PC
 SG_ E2P_SUMDATA1_Byte4_04 : 32|32@1+ (1,0) [0|4294967295] ""  MBMU,PC

BO_ 2483220117 E2P_SUMDATA1__05: 8 ETH
 SG_ E2P_SUMDATA1_Byte1_05 : 0|8@1+ (1,0) [0|255] ""  MBMU,PC
 SG_ E2P_SUMDATA1_Byte2_05 : 8|8@1+ (1,0) [0|255] ""  MBMU,PC
 SG_ E2P_SUMDATA1_Byte3_05 : 16|16@1+ (1,0) [0|65535] ""  MBMU,PC
 SG_ E2P_SUMDATA1_Byte4_05 : 32|32@1+ (1,0) [0|4294967295] ""  MBMU,PC

BO_ 2483220118 E2P_SUMDATA1__06: 8 ETH
 SG_ E2P_SUMDATA1_Byte1_06 : 0|8@1+ (1,0) [0|255] ""  MBMU,PC
 SG_ E2P_SUMDATA1_Byte2_06 : 8|8@1+ (1,0) [0|255] ""  MBMU,PC
 SG_ E2P_SUMDATA1_Byte3_06 : 16|16@1+ (1,0) [0|65535] ""  MBMU,PC
 SG_ E2P_SUMDATA1_Byte4_06 : 32|32@1+ (1,0) [0|4294967295] ""  MBMU,PC

BO_ 2483220119 E2P_SUMDATA1__07: 8 ETH
 SG_ E2P_SUMDATA1_Byte1_07 : 0|8@1+ (1,0) [0|255] ""  MBMU,PC
 SG_ E2P_SUMDATA1_Byte2_07 : 8|8@1+ (1,0) [0|255] ""  MBMU,PC
 SG_ E2P_SUMDATA1_Byte3_07 : 16|16@1+ (1,0) [0|65535] ""  MBMU,PC
 SG_ E2P_SUMDATA1_Byte4_07 : 32|32@1+ (1,0) [0|4294967295] ""  MBMU,PC

BO_ 2483220120 E2P_SUMDATA1__08: 8 ETH
 SG_ E2P_SUMDATA1_Byte1_08 : 0|8@1+ (1,0) [0|255] ""  MBMU,PC
 SG_ E2P_SUMDATA1_Byte2_08 : 8|8@1+ (1,0) [0|255] ""  MBMU,PC
 SG_ E2P_SUMDATA1_Byte3_08 : 16|16@1+ (1,0) [0|65535] ""  MBMU,PC
 SG_ E2P_SUMDATA1_Byte4_08 : 32|32@1+ (1,0) [0|4294967295] ""  MBMU,PC

BO_ 2483220121 E2P_SUMDATA1__09: 8 ETH
 SG_ E2P_SUMDATA1_Byte1_09 : 0|8@1+ (1,0) [0|255] ""  MBMU,PC
 SG_ E2P_SUMDATA1_Byte2_09 : 8|8@1+ (1,0) [0|255] ""  MBMU,PC
 SG_ E2P_SUMDATA1_Byte3_09 : 16|16@1+ (1,0) [0|65535] ""  MBMU,PC
 SG_ E2P_SUMDATA1_Byte4_09 : 32|32@1+ (1,0) [0|4294967295] ""  MBMU,PC

BO_ 2483220122 E2P_SUMDATA1__10: 8 ETH
 SG_ E2P_SUMDATA1_Byte1_10 : 0|8@1+ (1,0) [0|255] ""  MBMU,PC
 SG_ E2P_SUMDATA1_Byte2_10 : 8|8@1+ (1,0) [0|255] ""  MBMU,PC
 SG_ E2P_SUMDATA1_Byte3_10 : 16|16@1+ (1,0) [0|65535] ""  MBMU,PC
 SG_ E2P_SUMDATA1_Byte4_10 : 32|32@1+ (1,0) [0|4294967295] ""  MBMU,PC

BO_ 2483220123 E2P_SUMDATA1__11: 8 ETH
 SG_ E2P_SUMDATA1_Byte1_11 : 0|8@1+ (1,0) [0|255] ""  MBMU,PC
 SG_ E2P_SUMDATA1_Byte2_11 : 8|8@1+ (1,0) [0|255] ""  MBMU,PC
 SG_ E2P_SUMDATA1_Byte3_11 : 16|16@1+ (1,0) [0|65535] ""  MBMU,PC
 SG_ E2P_SUMDATA1_Byte4_11 : 32|32@1+ (1,0) [0|4294967295] ""  MBMU,PC

BO_ 2483220124 E2P_SUMDATA1__12: 8 ETH
 SG_ E2P_SUMDATA1_Byte1_12 : 0|8@1+ (1,0) [0|255] ""  MBMU,PC
 SG_ E2P_SUMDATA1_Byte2_12 : 8|8@1+ (1,0) [0|255] ""  MBMU,PC
 SG_ E2P_SUMDATA1_Byte3_12 : 16|16@1+ (1,0) [0|65535] ""  MBMU,PC
 SG_ E2P_SUMDATA1_Byte4_12 : 32|32@1+ (1,0) [0|4294967295] ""  MBMU,PC

BO_ 2483220125 E2P_SUMDATA1__13: 8 ETH
 SG_ E2P_SUMDATA1_Byte1_13 : 0|8@1+ (1,0) [0|255] ""  MBMU,PC
 SG_ E2P_SUMDATA1_Byte2_13 : 8|8@1+ (1,0) [0|255] ""  MBMU,PC
 SG_ E2P_SUMDATA1_Byte3_13 : 16|16@1+ (1,0) [0|65535] ""  MBMU,PC
 SG_ E2P_SUMDATA1_Byte4_13 : 32|32@1+ (1,0) [0|4294967295] ""  MBMU,PC

BO_ 2483220126 E2P_SUMDATA1__14: 8 ETH
 SG_ E2P_SUMDATA1_Byte1_14 : 0|8@1+ (1,0) [0|255] ""  MBMU,PC
 SG_ E2P_SUMDATA1_Byte2_14 : 8|8@1+ (1,0) [0|255] ""  MBMU,PC
 SG_ E2P_SUMDATA1_Byte3_14 : 16|16@1+ (1,0) [0|65535] ""  MBMU,PC
 SG_ E2P_SUMDATA1_Byte4_14 : 32|32@1+ (1,0) [0|4294967295] ""  MBMU,PC

BO_ 2483220127 E2P_SUMDATA1__15: 8 ETH
 SG_ E2P_SUMDATA1_Byte1_15 : 0|8@1+ (1,0) [0|255] ""  MBMU,PC
 SG_ E2P_SUMDATA1_Byte2_15 : 8|8@1+ (1,0) [0|255] ""  MBMU,PC
 SG_ E2P_SUMDATA1_Byte3_15 : 16|16@1+ (1,0) [0|65535] ""  MBMU,PC
 SG_ E2P_SUMDATA1_Byte4_15 : 32|32@1+ (1,0) [0|4294967295] ""  MBMU,PC

BO_ 2483220128 E2P_SUMDATA1__16: 8 ETH
 SG_ E2P_SUMDATA1_Byte1_16 : 0|8@1+ (1,0) [0|255] ""  MBMU,PC
 SG_ E2P_SUMDATA1_Byte2_16 : 8|8@1+ (1,0) [0|255] ""  MBMU,PC
 SG_ E2P_SUMDATA1_Byte3_16 : 16|16@1+ (1,0) [0|65535] ""  MBMU,PC
 SG_ E2P_SUMDATA1_Byte4_16 : 32|32@1+ (1,0) [0|4294967295] ""  MBMU,PC

BO_ 2483220129 E2P_SUMDATA1__17: 8 ETH
 SG_ E2P_SUMDATA1_Byte1_17 : 0|8@1+ (1,0) [0|255] ""  MBMU,PC
 SG_ E2P_SUMDATA1_Byte2_17 : 8|8@1+ (1,0) [0|255] ""  MBMU,PC
 SG_ E2P_SUMDATA1_Byte3_17 : 16|16@1+ (1,0) [0|65535] ""  MBMU,PC
 SG_ E2P_SUMDATA1_Byte4_17 : 32|32@1+ (1,0) [0|4294967295] ""  MBMU,PC

BO_ 2483220130 E2P_SUMDATA1__18: 8 ETH
 SG_ E2P_SUMDATA1_Byte1_18 : 0|8@1+ (1,0) [0|255] ""  MBMU,PC
 SG_ E2P_SUMDATA1_Byte2_18 : 8|8@1+ (1,0) [0|255] ""  MBMU,PC
 SG_ E2P_SUMDATA1_Byte3_18 : 16|16@1+ (1,0) [0|65535] ""  MBMU,PC
 SG_ E2P_SUMDATA1_Byte4_18 : 32|32@1+ (1,0) [0|4294967295] ""  MBMU,PC

BO_ 2483220131 E2P_SUMDATA1__19: 8 ETH
 SG_ E2P_SUMDATA1_Byte1_19 : 0|8@1+ (1,0) [0|255] ""  MBMU,PC
 SG_ E2P_SUMDATA1_Byte2_19 : 8|8@1+ (1,0) [0|255] ""  MBMU,PC
 SG_ E2P_SUMDATA1_Byte3_19 : 16|16@1+ (1,0) [0|65535] ""  MBMU,PC
 SG_ E2P_SUMDATA1_Byte4_19 : 32|32@1+ (1,0) [0|4294967295] ""  MBMU,PC

BO_ 2483220132 E2P_SUMDATA1__20: 8 ETH
 SG_ E2P_SUMDATA1_Byte1_20 : 0|8@1+ (1,0) [0|255] ""  MBMU,PC
 SG_ E2P_SUMDATA1_Byte2_20 : 8|8@1+ (1,0) [0|255] ""  MBMU,PC
 SG_ E2P_SUMDATA1_Byte3_20 : 16|16@1+ (1,0) [0|65535] ""  MBMU,PC
 SG_ E2P_SUMDATA1_Byte4_20 : 32|32@1+ (1,0) [0|4294967295] ""  MBMU,PC

BO_ 2483220133 E2P_SUMDATA1__21: 8 ETH
 SG_ E2P_SUMDATA1_Byte1_21 : 0|8@1+ (1,0) [0|255] ""  MBMU,PC
 SG_ E2P_SUMDATA1_Byte2_21 : 8|8@1+ (1,0) [0|255] ""  MBMU,PC
 SG_ E2P_SUMDATA1_Byte3_21 : 16|16@1+ (1,0) [0|65535] ""  MBMU,PC
 SG_ E2P_SUMDATA1_Byte4_21 : 32|32@1+ (1,0) [0|4294967295] ""  MBMU,PC

BO_ 2483220134 E2P_SUMDATA1__22: 8 ETH
 SG_ E2P_SUMDATA1_Byte1_22 : 0|8@1+ (1,0) [0|255] ""  MBMU,PC
 SG_ E2P_SUMDATA1_Byte2_22 : 8|8@1+ (1,0) [0|255] ""  MBMU,PC
 SG_ E2P_SUMDATA1_Byte3_22 : 16|16@1+ (1,0) [0|65535] ""  MBMU,PC
 SG_ E2P_SUMDATA1_Byte4_22 : 32|32@1+ (1,0) [0|4294967295] ""  MBMU,PC

BO_ 2483220135 E2P_SUMDATA1__23: 8 ETH
 SG_ E2P_SUMDATA1_Byte1_23 : 0|8@1+ (1,0) [0|255] ""  MBMU,PC
 SG_ E2P_SUMDATA1_Byte2_23 : 8|8@1+ (1,0) [0|255] ""  MBMU,PC
 SG_ E2P_SUMDATA1_Byte3_23 : 16|16@1+ (1,0) [0|65535] ""  MBMU,PC
 SG_ E2P_SUMDATA1_Byte4_23 : 32|32@1+ (1,0) [0|4294967295] ""  MBMU,PC

BO_ 2483220136 E2P_SUMDATA1__24: 8 ETH
 SG_ E2P_SUMDATA1_Byte1_24 : 0|8@1+ (1,0) [0|255] ""  MBMU,PC
 SG_ E2P_SUMDATA1_Byte2_24 : 8|8@1+ (1,0) [0|255] ""  MBMU,PC
 SG_ E2P_SUMDATA1_Byte3_24 : 16|16@1+ (1,0) [0|65535] ""  MBMU,PC
 SG_ E2P_SUMDATA1_Byte4_24 : 32|32@1+ (1,0) [0|4294967295] ""  MBMU,PC

BO_ 2483220137 E2P_SUMDATA1__25: 8 ETH
 SG_ E2P_SUMDATA1_Byte1_25 : 0|8@1+ (1,0) [0|255] ""  MBMU,PC
 SG_ E2P_SUMDATA1_Byte2_25 : 8|8@1+ (1,0) [0|255] ""  MBMU,PC
 SG_ E2P_SUMDATA1_Byte3_25 : 16|16@1+ (1,0) [0|65535] ""  MBMU,PC
 SG_ E2P_SUMDATA1_Byte4_25 : 32|32@1+ (1,0) [0|4294967295] ""  MBMU,PC

BO_ 2483220138 E2P_SUMDATA1__26: 8 ETH
 SG_ E2P_SUMDATA1_Byte1_26 : 0|8@1+ (1,0) [0|255] ""  MBMU,PC
 SG_ E2P_SUMDATA1_Byte2_26 : 8|8@1+ (1,0) [0|255] ""  MBMU,PC
 SG_ E2P_SUMDATA1_Byte3_26 : 16|16@1+ (1,0) [0|65535] ""  MBMU,PC
 SG_ E2P_SUMDATA1_Byte4_26 : 32|32@1+ (1,0) [0|4294967295] ""  MBMU,PC

BO_ 2483220139 E2P_SUMDATA1__27: 8 ETH
 SG_ E2P_SUMDATA1_Byte1_27 : 0|8@1+ (1,0) [0|255] ""  MBMU,PC
 SG_ E2P_SUMDATA1_Byte2_27 : 8|8@1+ (1,0) [0|255] ""  MBMU,PC
 SG_ E2P_SUMDATA1_Byte3_27 : 16|16@1+ (1,0) [0|65535] ""  MBMU,PC
 SG_ E2P_SUMDATA1_Byte4_27 : 32|32@1+ (1,0) [0|4294967295] ""  MBMU,PC

BO_ 2483220140 E2P_SUMDATA1__28: 8 ETH
 SG_ E2P_SUMDATA1_Byte1_28 : 0|8@1+ (1,0) [0|255] ""  MBMU,PC
 SG_ E2P_SUMDATA1_Byte2_28 : 8|8@1+ (1,0) [0|255] ""  MBMU,PC
 SG_ E2P_SUMDATA1_Byte3_28 : 16|16@1+ (1,0) [0|65535] ""  MBMU,PC
 SG_ E2P_SUMDATA1_Byte4_28 : 32|32@1+ (1,0) [0|4294967295] ""  MBMU,PC

BO_ 2483220141 E2P_SUMDATA1__29: 8 ETH
 SG_ E2P_SUMDATA1_Byte1_29 : 0|8@1+ (1,0) [0|255] ""  MBMU,PC
 SG_ E2P_SUMDATA1_Byte2_29 : 8|8@1+ (1,0) [0|255] ""  MBMU,PC
 SG_ E2P_SUMDATA1_Byte3_29 : 16|16@1+ (1,0) [0|65535] ""  MBMU,PC
 SG_ E2P_SUMDATA1_Byte4_29 : 32|32@1+ (1,0) [0|4294967295] ""  MBMU,PC

BO_ 2483220142 E2P_SUMDATA1__30: 8 ETH
 SG_ E2P_SUMDATA1_Byte1_30 : 0|8@1+ (1,0) [0|255] ""  MBMU,PC
 SG_ E2P_SUMDATA1_Byte2_30 : 8|8@1+ (1,0) [0|255] ""  MBMU,PC
 SG_ E2P_SUMDATA1_Byte3_30 : 16|16@1+ (1,0) [0|65535] ""  MBMU,PC
 SG_ E2P_SUMDATA1_Byte4_30 : 32|32@1+ (1,0) [0|4294967295] ""  MBMU,PC

BO_ 2483220143 E2P_SUMDATA1__31: 8 ETH
 SG_ E2P_SUMDATA1_Byte1_31 : 0|8@1+ (1,0) [0|255] ""  MBMU,PC
 SG_ E2P_SUMDATA1_Byte2_31 : 8|8@1+ (1,0) [0|255] ""  MBMU,PC
 SG_ E2P_SUMDATA1_Byte3_31 : 16|16@1+ (1,0) [0|65535] ""  MBMU,PC
 SG_ E2P_SUMDATA1_Byte4_31 : 32|32@1+ (1,0) [0|4294967295] ""  MBMU,PC

BO_ 2483089041 E2P_Response__01: 8 ETH
 SG_ E2P_Response_Byte1_01 : 0|8@1+ (1,0) [0|255] ""  PC
 SG_ E2P_Response_Byte2_01 : 8|8@1+ (1,0) [0|255] ""  PC
 SG_ E2P_Response_Byte3_01 : 16|8@1+ (1,0) [0|255] ""  PC
 SG_ E2P_Response_Byte4_01 : 24|8@1+ (1,0) [0|255] ""  PC
 SG_ E2P_Response_Byte5_01 : 32|8@1+ (1,0) [0|255] ""  PC
 SG_ E2P_Response_Byte6_01 : 40|8@1+ (1,0) [0|255] ""  PC
 SG_ E2P_Response_Byte7_01 : 48|8@1+ (1,0) [0|255] ""  PC
 SG_ E2P_Response_Byte8_01 : 56|8@1+ (1,0) [0|255] ""  PC

BO_ 2483089042 E2P_Response__02: 8 ETH
 SG_ E2P_Response_Byte1_02 : 0|8@1+ (1,0) [0|255] ""  PC
 SG_ E2P_Response_Byte2_02 : 8|8@1+ (1,0) [0|255] ""  PC
 SG_ E2P_Response_Byte3_02 : 16|8@1+ (1,0) [0|255] ""  PC
 SG_ E2P_Response_Byte4_02 : 24|8@1+ (1,0) [0|255] ""  PC
 SG_ E2P_Response_Byte5_02 : 32|8@1+ (1,0) [0|255] ""  PC
 SG_ E2P_Response_Byte6_02 : 40|8@1+ (1,0) [0|255] ""  PC
 SG_ E2P_Response_Byte7_02 : 48|8@1+ (1,0) [0|255] ""  PC
 SG_ E2P_Response_Byte8_02 : 56|8@1+ (1,0) [0|255] ""  PC

BO_ 2483089043 E2P_Response__03: 8 ETH
 SG_ E2P_Response_Byte1_03 : 0|8@1+ (1,0) [0|255] ""  PC
 SG_ E2P_Response_Byte2_03 : 8|8@1+ (1,0) [0|255] ""  PC
 SG_ E2P_Response_Byte3_03 : 16|8@1+ (1,0) [0|255] ""  PC
 SG_ E2P_Response_Byte4_03 : 24|8@1+ (1,0) [0|255] ""  PC
 SG_ E2P_Response_Byte5_03 : 32|8@1+ (1,0) [0|255] ""  PC
 SG_ E2P_Response_Byte6_03 : 40|8@1+ (1,0) [0|255] ""  PC
 SG_ E2P_Response_Byte7_03 : 48|8@1+ (1,0) [0|255] ""  PC
 SG_ E2P_Response_Byte8_03 : 56|8@1+ (1,0) [0|255] ""  PC

BO_ 2483089044 E2P_Response__04: 8 ETH
 SG_ E2P_Response_Byte1_04 : 0|8@1+ (1,0) [0|255] ""  PC
 SG_ E2P_Response_Byte2_04 : 8|8@1+ (1,0) [0|255] ""  PC
 SG_ E2P_Response_Byte3_04 : 16|8@1+ (1,0) [0|255] ""  PC
 SG_ E2P_Response_Byte4_04 : 24|8@1+ (1,0) [0|255] ""  PC
 SG_ E2P_Response_Byte5_04 : 32|8@1+ (1,0) [0|255] ""  PC
 SG_ E2P_Response_Byte6_04 : 40|8@1+ (1,0) [0|255] ""  PC
 SG_ E2P_Response_Byte7_04 : 48|8@1+ (1,0) [0|255] ""  PC
 SG_ E2P_Response_Byte8_04 : 56|8@1+ (1,0) [0|255] ""  PC

BO_ 2483089045 E2P_Response__05: 8 ETH
 SG_ E2P_Response_Byte1_05 : 0|8@1+ (1,0) [0|255] ""  PC
 SG_ E2P_Response_Byte2_05 : 8|8@1+ (1,0) [0|255] ""  PC
 SG_ E2P_Response_Byte3_05 : 16|8@1+ (1,0) [0|255] ""  PC
 SG_ E2P_Response_Byte4_05 : 24|8@1+ (1,0) [0|255] ""  PC
 SG_ E2P_Response_Byte5_05 : 32|8@1+ (1,0) [0|255] ""  PC
 SG_ E2P_Response_Byte6_05 : 40|8@1+ (1,0) [0|255] ""  PC
 SG_ E2P_Response_Byte7_05 : 48|8@1+ (1,0) [0|255] ""  PC
 SG_ E2P_Response_Byte8_05 : 56|8@1+ (1,0) [0|255] ""  PC

BO_ 2483089046 E2P_Response__06: 8 ETH
 SG_ E2P_Response_Byte1_06 : 0|8@1+ (1,0) [0|255] ""  PC
 SG_ E2P_Response_Byte2_06 : 8|8@1+ (1,0) [0|255] ""  PC
 SG_ E2P_Response_Byte3_06 : 16|8@1+ (1,0) [0|255] ""  PC
 SG_ E2P_Response_Byte4_06 : 24|8@1+ (1,0) [0|255] ""  PC
 SG_ E2P_Response_Byte5_06 : 32|8@1+ (1,0) [0|255] ""  PC
 SG_ E2P_Response_Byte6_06 : 40|8@1+ (1,0) [0|255] ""  PC
 SG_ E2P_Response_Byte7_06 : 48|8@1+ (1,0) [0|255] ""  PC
 SG_ E2P_Response_Byte8_06 : 56|8@1+ (1,0) [0|255] ""  PC

BO_ 2483089047 E2P_Response__07: 8 ETH
 SG_ E2P_Response_Byte1_07 : 0|8@1+ (1,0) [0|255] ""  PC
 SG_ E2P_Response_Byte2_07 : 8|8@1+ (1,0) [0|255] ""  PC
 SG_ E2P_Response_Byte3_07 : 16|8@1+ (1,0) [0|255] ""  PC
 SG_ E2P_Response_Byte4_07 : 24|8@1+ (1,0) [0|255] ""  PC
 SG_ E2P_Response_Byte5_07 : 32|8@1+ (1,0) [0|255] ""  PC
 SG_ E2P_Response_Byte6_07 : 40|8@1+ (1,0) [0|255] ""  PC
 SG_ E2P_Response_Byte7_07 : 48|8@1+ (1,0) [0|255] ""  PC
 SG_ E2P_Response_Byte8_07 : 56|8@1+ (1,0) [0|255] ""  PC

BO_ 2483089048 E2P_Response__08: 8 ETH
 SG_ E2P_Response_Byte1_08 : 0|8@1+ (1,0) [0|255] ""  PC
 SG_ E2P_Response_Byte2_08 : 8|8@1+ (1,0) [0|255] ""  PC
 SG_ E2P_Response_Byte3_08 : 16|8@1+ (1,0) [0|255] ""  PC
 SG_ E2P_Response_Byte4_08 : 24|8@1+ (1,0) [0|255] ""  PC
 SG_ E2P_Response_Byte5_08 : 32|8@1+ (1,0) [0|255] ""  PC
 SG_ E2P_Response_Byte6_08 : 40|8@1+ (1,0) [0|255] ""  PC
 SG_ E2P_Response_Byte7_08 : 48|8@1+ (1,0) [0|255] ""  PC
 SG_ E2P_Response_Byte8_08 : 56|8@1+ (1,0) [0|255] ""  PC

BO_ 2483089049 E2P_Response__09: 8 ETH
 SG_ E2P_Response_Byte1_09 : 0|8@1+ (1,0) [0|255] ""  PC
 SG_ E2P_Response_Byte2_09 : 8|8@1+ (1,0) [0|255] ""  PC
 SG_ E2P_Response_Byte3_09 : 16|8@1+ (1,0) [0|255] ""  PC
 SG_ E2P_Response_Byte4_09 : 24|8@1+ (1,0) [0|255] ""  PC
 SG_ E2P_Response_Byte5_09 : 32|8@1+ (1,0) [0|255] ""  PC
 SG_ E2P_Response_Byte6_09 : 40|8@1+ (1,0) [0|255] ""  PC
 SG_ E2P_Response_Byte7_09 : 48|8@1+ (1,0) [0|255] ""  PC
 SG_ E2P_Response_Byte8_09 : 56|8@1+ (1,0) [0|255] ""  PC

BO_ 2483089050 E2P_Response__10: 8 ETH
 SG_ E2P_Response_Byte1_10 : 0|8@1+ (1,0) [0|255] ""  PC
 SG_ E2P_Response_Byte2_10 : 8|8@1+ (1,0) [0|255] ""  PC
 SG_ E2P_Response_Byte3_10 : 16|8@1+ (1,0) [0|255] ""  PC
 SG_ E2P_Response_Byte4_10 : 24|8@1+ (1,0) [0|255] ""  PC
 SG_ E2P_Response_Byte5_10 : 32|8@1+ (1,0) [0|255] ""  PC
 SG_ E2P_Response_Byte6_10 : 40|8@1+ (1,0) [0|255] ""  PC
 SG_ E2P_Response_Byte7_10 : 48|8@1+ (1,0) [0|255] ""  PC
 SG_ E2P_Response_Byte8_10 : 56|8@1+ (1,0) [0|255] ""  PC

BO_ 2483089051 E2P_Response__11: 8 ETH
 SG_ E2P_Response_Byte1_11 : 0|8@1+ (1,0) [0|255] ""  PC
 SG_ E2P_Response_Byte2_11 : 8|8@1+ (1,0) [0|255] ""  PC
 SG_ E2P_Response_Byte3_11 : 16|8@1+ (1,0) [0|255] ""  PC
 SG_ E2P_Response_Byte4_11 : 24|8@1+ (1,0) [0|255] ""  PC
 SG_ E2P_Response_Byte5_11 : 32|8@1+ (1,0) [0|255] ""  PC
 SG_ E2P_Response_Byte6_11 : 40|8@1+ (1,0) [0|255] ""  PC
 SG_ E2P_Response_Byte7_11 : 48|8@1+ (1,0) [0|255] ""  PC
 SG_ E2P_Response_Byte8_11 : 56|8@1+ (1,0) [0|255] ""  PC

BO_ 2483089052 E2P_Response__12: 8 ETH
 SG_ E2P_Response_Byte1_12 : 0|8@1+ (1,0) [0|255] ""  PC
 SG_ E2P_Response_Byte2_12 : 8|8@1+ (1,0) [0|255] ""  PC
 SG_ E2P_Response_Byte3_12 : 16|8@1+ (1,0) [0|255] ""  PC
 SG_ E2P_Response_Byte4_12 : 24|8@1+ (1,0) [0|255] ""  PC
 SG_ E2P_Response_Byte5_12 : 32|8@1+ (1,0) [0|255] ""  PC
 SG_ E2P_Response_Byte6_12 : 40|8@1+ (1,0) [0|255] ""  PC
 SG_ E2P_Response_Byte7_12 : 48|8@1+ (1,0) [0|255] ""  PC
 SG_ E2P_Response_Byte8_12 : 56|8@1+ (1,0) [0|255] ""  PC

BO_ 2483089053 E2P_Response__13: 8 ETH
 SG_ E2P_Response_Byte1_13 : 0|8@1+ (1,0) [0|255] ""  PC
 SG_ E2P_Response_Byte2_13 : 8|8@1+ (1,0) [0|255] ""  PC
 SG_ E2P_Response_Byte3_13 : 16|8@1+ (1,0) [0|255] ""  PC
 SG_ E2P_Response_Byte4_13 : 24|8@1+ (1,0) [0|255] ""  PC
 SG_ E2P_Response_Byte5_13 : 32|8@1+ (1,0) [0|255] ""  PC
 SG_ E2P_Response_Byte6_13 : 40|8@1+ (1,0) [0|255] ""  PC
 SG_ E2P_Response_Byte7_13 : 48|8@1+ (1,0) [0|255] ""  PC
 SG_ E2P_Response_Byte8_13 : 56|8@1+ (1,0) [0|255] ""  PC

BO_ 2483089054 E2P_Response__14: 8 ETH
 SG_ E2P_Response_Byte1_14 : 0|8@1+ (1,0) [0|255] ""  PC
 SG_ E2P_Response_Byte2_14 : 8|8@1+ (1,0) [0|255] ""  PC
 SG_ E2P_Response_Byte3_14 : 16|8@1+ (1,0) [0|255] ""  PC
 SG_ E2P_Response_Byte4_14 : 24|8@1+ (1,0) [0|255] ""  PC
 SG_ E2P_Response_Byte5_14 : 32|8@1+ (1,0) [0|255] ""  PC
 SG_ E2P_Response_Byte6_14 : 40|8@1+ (1,0) [0|255] ""  PC
 SG_ E2P_Response_Byte7_14 : 48|8@1+ (1,0) [0|255] ""  PC
 SG_ E2P_Response_Byte8_14 : 56|8@1+ (1,0) [0|255] ""  PC

BO_ 2483089055 E2P_Response__15: 8 ETH
 SG_ E2P_Response_Byte1_15 : 0|8@1+ (1,0) [0|255] ""  PC
 SG_ E2P_Response_Byte2_15 : 8|8@1+ (1,0) [0|255] ""  PC
 SG_ E2P_Response_Byte3_15 : 16|8@1+ (1,0) [0|255] ""  PC
 SG_ E2P_Response_Byte4_15 : 24|8@1+ (1,0) [0|255] ""  PC
 SG_ E2P_Response_Byte5_15 : 32|8@1+ (1,0) [0|255] ""  PC
 SG_ E2P_Response_Byte6_15 : 40|8@1+ (1,0) [0|255] ""  PC
 SG_ E2P_Response_Byte7_15 : 48|8@1+ (1,0) [0|255] ""  PC
 SG_ E2P_Response_Byte8_15 : 56|8@1+ (1,0) [0|255] ""  PC

BO_ 2483089056 E2P_Response__16: 8 ETH
 SG_ E2P_Response_Byte1_16 : 0|8@1+ (1,0) [0|255] ""  PC
 SG_ E2P_Response_Byte2_16 : 8|8@1+ (1,0) [0|255] ""  PC
 SG_ E2P_Response_Byte3_16 : 16|8@1+ (1,0) [0|255] ""  PC
 SG_ E2P_Response_Byte4_16 : 24|8@1+ (1,0) [0|255] ""  PC
 SG_ E2P_Response_Byte5_16 : 32|8@1+ (1,0) [0|255] ""  PC
 SG_ E2P_Response_Byte6_16 : 40|8@1+ (1,0) [0|255] ""  PC
 SG_ E2P_Response_Byte7_16 : 48|8@1+ (1,0) [0|255] ""  PC
 SG_ E2P_Response_Byte8_16 : 56|8@1+ (1,0) [0|255] ""  PC

BO_ 2483089057 E2P_Response__17: 8 ETH
 SG_ E2P_Response_Byte1_17 : 0|8@1+ (1,0) [0|255] ""  PC
 SG_ E2P_Response_Byte2_17 : 8|8@1+ (1,0) [0|255] ""  PC
 SG_ E2P_Response_Byte3_17 : 16|8@1+ (1,0) [0|255] ""  PC
 SG_ E2P_Response_Byte4_17 : 24|8@1+ (1,0) [0|255] ""  PC
 SG_ E2P_Response_Byte5_17 : 32|8@1+ (1,0) [0|255] ""  PC
 SG_ E2P_Response_Byte6_17 : 40|8@1+ (1,0) [0|255] ""  PC
 SG_ E2P_Response_Byte7_17 : 48|8@1+ (1,0) [0|255] ""  PC
 SG_ E2P_Response_Byte8_17 : 56|8@1+ (1,0) [0|255] ""  PC

BO_ 2483089058 E2P_Response__18: 8 ETH
 SG_ E2P_Response_Byte1_18 : 0|8@1+ (1,0) [0|255] ""  PC
 SG_ E2P_Response_Byte2_18 : 8|8@1+ (1,0) [0|255] ""  PC
 SG_ E2P_Response_Byte3_18 : 16|8@1+ (1,0) [0|255] ""  PC
 SG_ E2P_Response_Byte4_18 : 24|8@1+ (1,0) [0|255] ""  PC
 SG_ E2P_Response_Byte5_18 : 32|8@1+ (1,0) [0|255] ""  PC
 SG_ E2P_Response_Byte6_18 : 40|8@1+ (1,0) [0|255] ""  PC
 SG_ E2P_Response_Byte7_18 : 48|8@1+ (1,0) [0|255] ""  PC
 SG_ E2P_Response_Byte8_18 : 56|8@1+ (1,0) [0|255] ""  PC

BO_ 2483089059 E2P_Response__19: 8 ETH
 SG_ E2P_Response_Byte1_19 : 0|8@1+ (1,0) [0|255] ""  PC
 SG_ E2P_Response_Byte2_19 : 8|8@1+ (1,0) [0|255] ""  PC
 SG_ E2P_Response_Byte3_19 : 16|8@1+ (1,0) [0|255] ""  PC
 SG_ E2P_Response_Byte4_19 : 24|8@1+ (1,0) [0|255] ""  PC
 SG_ E2P_Response_Byte5_19 : 32|8@1+ (1,0) [0|255] ""  PC
 SG_ E2P_Response_Byte6_19 : 40|8@1+ (1,0) [0|255] ""  PC
 SG_ E2P_Response_Byte7_19 : 48|8@1+ (1,0) [0|255] ""  PC
 SG_ E2P_Response_Byte8_19 : 56|8@1+ (1,0) [0|255] ""  PC

BO_ 2483089060 E2P_Response__20: 8 ETH
 SG_ E2P_Response_Byte1_20 : 0|8@1+ (1,0) [0|255] ""  PC
 SG_ E2P_Response_Byte2_20 : 8|8@1+ (1,0) [0|255] ""  PC
 SG_ E2P_Response_Byte3_20 : 16|8@1+ (1,0) [0|255] ""  PC
 SG_ E2P_Response_Byte4_20 : 24|8@1+ (1,0) [0|255] ""  PC
 SG_ E2P_Response_Byte5_20 : 32|8@1+ (1,0) [0|255] ""  PC
 SG_ E2P_Response_Byte6_20 : 40|8@1+ (1,0) [0|255] ""  PC
 SG_ E2P_Response_Byte7_20 : 48|8@1+ (1,0) [0|255] ""  PC
 SG_ E2P_Response_Byte8_20 : 56|8@1+ (1,0) [0|255] ""  PC

BO_ 2483089061 E2P_Response__21: 8 ETH
 SG_ E2P_Response_Byte1_21 : 0|8@1+ (1,0) [0|255] ""  PC
 SG_ E2P_Response_Byte2_21 : 8|8@1+ (1,0) [0|255] ""  PC
 SG_ E2P_Response_Byte3_21 : 16|8@1+ (1,0) [0|255] ""  PC
 SG_ E2P_Response_Byte4_21 : 24|8@1+ (1,0) [0|255] ""  PC
 SG_ E2P_Response_Byte5_21 : 32|8@1+ (1,0) [0|255] ""  PC
 SG_ E2P_Response_Byte6_21 : 40|8@1+ (1,0) [0|255] ""  PC
 SG_ E2P_Response_Byte7_21 : 48|8@1+ (1,0) [0|255] ""  PC
 SG_ E2P_Response_Byte8_21 : 56|8@1+ (1,0) [0|255] ""  PC

BO_ 2483089062 E2P_Response__22: 8 ETH
 SG_ E2P_Response_Byte1_22 : 0|8@1+ (1,0) [0|255] ""  PC
 SG_ E2P_Response_Byte2_22 : 8|8@1+ (1,0) [0|255] ""  PC
 SG_ E2P_Response_Byte3_22 : 16|8@1+ (1,0) [0|255] ""  PC
 SG_ E2P_Response_Byte4_22 : 24|8@1+ (1,0) [0|255] ""  PC
 SG_ E2P_Response_Byte5_22 : 32|8@1+ (1,0) [0|255] ""  PC
 SG_ E2P_Response_Byte6_22 : 40|8@1+ (1,0) [0|255] ""  PC
 SG_ E2P_Response_Byte7_22 : 48|8@1+ (1,0) [0|255] ""  PC
 SG_ E2P_Response_Byte8_22 : 56|8@1+ (1,0) [0|255] ""  PC

BO_ 2483089063 E2P_Response__23: 8 ETH
 SG_ E2P_Response_Byte1_23 : 0|8@1+ (1,0) [0|255] ""  PC
 SG_ E2P_Response_Byte2_23 : 8|8@1+ (1,0) [0|255] ""  PC
 SG_ E2P_Response_Byte3_23 : 16|8@1+ (1,0) [0|255] ""  PC
 SG_ E2P_Response_Byte4_23 : 24|8@1+ (1,0) [0|255] ""  PC
 SG_ E2P_Response_Byte5_23 : 32|8@1+ (1,0) [0|255] ""  PC
 SG_ E2P_Response_Byte6_23 : 40|8@1+ (1,0) [0|255] ""  PC
 SG_ E2P_Response_Byte7_23 : 48|8@1+ (1,0) [0|255] ""  PC
 SG_ E2P_Response_Byte8_23 : 56|8@1+ (1,0) [0|255] ""  PC

BO_ 2483089064 E2P_Response__24: 8 ETH
 SG_ E2P_Response_Byte1_24 : 0|8@1+ (1,0) [0|255] ""  PC
 SG_ E2P_Response_Byte2_24 : 8|8@1+ (1,0) [0|255] ""  PC
 SG_ E2P_Response_Byte3_24 : 16|8@1+ (1,0) [0|255] ""  PC
 SG_ E2P_Response_Byte4_24 : 24|8@1+ (1,0) [0|255] ""  PC
 SG_ E2P_Response_Byte5_24 : 32|8@1+ (1,0) [0|255] ""  PC
 SG_ E2P_Response_Byte6_24 : 40|8@1+ (1,0) [0|255] ""  PC
 SG_ E2P_Response_Byte7_24 : 48|8@1+ (1,0) [0|255] ""  PC
 SG_ E2P_Response_Byte8_24 : 56|8@1+ (1,0) [0|255] ""  PC

BO_ 2483089065 E2P_Response__25: 8 ETH
 SG_ E2P_Response_Byte1_25 : 0|8@1+ (1,0) [0|255] ""  PC
 SG_ E2P_Response_Byte2_25 : 8|8@1+ (1,0) [0|255] ""  PC
 SG_ E2P_Response_Byte3_25 : 16|8@1+ (1,0) [0|255] ""  PC
 SG_ E2P_Response_Byte4_25 : 24|8@1+ (1,0) [0|255] ""  PC
 SG_ E2P_Response_Byte5_25 : 32|8@1+ (1,0) [0|255] ""  PC
 SG_ E2P_Response_Byte6_25 : 40|8@1+ (1,0) [0|255] ""  PC
 SG_ E2P_Response_Byte7_25 : 48|8@1+ (1,0) [0|255] ""  PC
 SG_ E2P_Response_Byte8_25 : 56|8@1+ (1,0) [0|255] ""  PC

BO_ 2483089066 E2P_Response__26: 8 ETH
 SG_ E2P_Response_Byte1_26 : 0|8@1+ (1,0) [0|255] ""  PC
 SG_ E2P_Response_Byte2_26 : 8|8@1+ (1,0) [0|255] ""  PC
 SG_ E2P_Response_Byte3_26 : 16|8@1+ (1,0) [0|255] ""  PC
 SG_ E2P_Response_Byte4_26 : 24|8@1+ (1,0) [0|255] ""  PC
 SG_ E2P_Response_Byte5_26 : 32|8@1+ (1,0) [0|255] ""  PC
 SG_ E2P_Response_Byte6_26 : 40|8@1+ (1,0) [0|255] ""  PC
 SG_ E2P_Response_Byte7_26 : 48|8@1+ (1,0) [0|255] ""  PC
 SG_ E2P_Response_Byte8_26 : 56|8@1+ (1,0) [0|255] ""  PC

BO_ 2483089067 E2P_Response__27: 8 ETH
 SG_ E2P_Response_Byte1_27 : 0|8@1+ (1,0) [0|255] ""  PC
 SG_ E2P_Response_Byte2_27 : 8|8@1+ (1,0) [0|255] ""  PC
 SG_ E2P_Response_Byte3_27 : 16|8@1+ (1,0) [0|255] ""  PC
 SG_ E2P_Response_Byte4_27 : 24|8@1+ (1,0) [0|255] ""  PC
 SG_ E2P_Response_Byte5_27 : 32|8@1+ (1,0) [0|255] ""  PC
 SG_ E2P_Response_Byte6_27 : 40|8@1+ (1,0) [0|255] ""  PC
 SG_ E2P_Response_Byte7_27 : 48|8@1+ (1,0) [0|255] ""  PC
 SG_ E2P_Response_Byte8_27 : 56|8@1+ (1,0) [0|255] ""  PC

BO_ 2483089068 E2P_Response__28: 8 ETH
 SG_ E2P_Response_Byte1_28 : 0|8@1+ (1,0) [0|255] ""  PC
 SG_ E2P_Response_Byte2_28 : 8|8@1+ (1,0) [0|255] ""  PC
 SG_ E2P_Response_Byte3_28 : 16|8@1+ (1,0) [0|255] ""  PC
 SG_ E2P_Response_Byte4_28 : 24|8@1+ (1,0) [0|255] ""  PC
 SG_ E2P_Response_Byte5_28 : 32|8@1+ (1,0) [0|255] ""  PC
 SG_ E2P_Response_Byte6_28 : 40|8@1+ (1,0) [0|255] ""  PC
 SG_ E2P_Response_Byte7_28 : 48|8@1+ (1,0) [0|255] ""  PC
 SG_ E2P_Response_Byte8_28 : 56|8@1+ (1,0) [0|255] ""  PC

BO_ 2483089069 E2P_Response__29: 8 ETH
 SG_ E2P_Response_Byte1_29 : 0|8@1+ (1,0) [0|255] ""  PC
 SG_ E2P_Response_Byte2_29 : 8|8@1+ (1,0) [0|255] ""  PC
 SG_ E2P_Response_Byte3_29 : 16|8@1+ (1,0) [0|255] ""  PC
 SG_ E2P_Response_Byte4_29 : 24|8@1+ (1,0) [0|255] ""  PC
 SG_ E2P_Response_Byte5_29 : 32|8@1+ (1,0) [0|255] ""  PC
 SG_ E2P_Response_Byte6_29 : 40|8@1+ (1,0) [0|255] ""  PC
 SG_ E2P_Response_Byte7_29 : 48|8@1+ (1,0) [0|255] ""  PC
 SG_ E2P_Response_Byte8_29 : 56|8@1+ (1,0) [0|255] ""  PC

BO_ 2483089070 E2P_Response__30: 8 ETH
 SG_ E2P_Response_Byte1_30 : 0|8@1+ (1,0) [0|255] ""  PC
 SG_ E2P_Response_Byte2_30 : 8|8@1+ (1,0) [0|255] ""  PC
 SG_ E2P_Response_Byte3_30 : 16|8@1+ (1,0) [0|255] ""  PC
 SG_ E2P_Response_Byte4_30 : 24|8@1+ (1,0) [0|255] ""  PC
 SG_ E2P_Response_Byte5_30 : 32|8@1+ (1,0) [0|255] ""  PC
 SG_ E2P_Response_Byte6_30 : 40|8@1+ (1,0) [0|255] ""  PC
 SG_ E2P_Response_Byte7_30 : 48|8@1+ (1,0) [0|255] ""  PC
 SG_ E2P_Response_Byte8_30 : 56|8@1+ (1,0) [0|255] ""  PC

BO_ 2483089071 E2P_Response__31: 8 ETH
 SG_ E2P_Response_Byte1_31 : 0|8@1+ (1,0) [0|255] ""  PC
 SG_ E2P_Response_Byte2_31 : 8|8@1+ (1,0) [0|255] ""  PC
 SG_ E2P_Response_Byte3_31 : 16|8@1+ (1,0) [0|255] ""  PC
 SG_ E2P_Response_Byte4_31 : 24|8@1+ (1,0) [0|255] ""  PC
 SG_ E2P_Response_Byte5_31 : 32|8@1+ (1,0) [0|255] ""  PC
 SG_ E2P_Response_Byte6_31 : 40|8@1+ (1,0) [0|255] ""  PC
 SG_ E2P_Response_Byte7_31 : 48|8@1+ (1,0) [0|255] ""  PC
 SG_ E2P_Response_Byte8_31 : 56|8@1+ (1,0) [0|255] ""  PC

BO_ 2148826945 M2D_CMD1__01: 8 MBMU
 SG_ M2D_CMD1_CRC_01 : 0|8@1+ (1,0) [0|255] ""  DCDC
 SG_ M2D_CMD1_DCDCSerialNum_01 : 8|4@1+ (1,0) [0|15] ""  DCDC
 SG_ M2D_CMD1_DCDCEnable_01 : 12|1@1+ (1,0) [0|1] ""  DCDC
 SG_ M2D_CMD1_Reserved1_01 : 13|3@1+ (1,0) [0|7] ""  DCDC
 SG_ M2D_CMD1_DCDCWrkMdSwtch_01 : 16|2@1+ (1,0) [0|3] ""  DCDC
 SG_ M2D_CMD1_DCDCWrkMdSet_01 : 18|2@1+ (1,0) [0|3] ""  DCDC
 SG_ M2D_CMD1_Reserved2_01 : 20|3@1+ (1,0) [0|7] ""  DCDC
 SG_ M2D_CMD1_DCDCOutputCrrntSet_01 : 23|16@1+ (0.05,-2000) [-2000|1276.75] "A"  DCDC
 SG_ M2D_CMD1_DCDCOutputVltge_Set_01 : 39|12@1+ (0.1,-200) [-200|209.5] "V"  DCDC
 SG_ M2D_CMD1_Reserved3_01 : 51|4@1+ (1,0) [0|15] ""  DCDC
 SG_ M2D_CMD1_CommunicationState_01 : 55|2@1+ (1,0) [0|3] ""  DCDC
 SG_ M2D_CMD1_DCDCFaultClear_01 : 57|1@1+ (1,0) [0|1] ""  DCDC
 SG_ M2D_CMD1_PCSOperationState_01 : 58|2@1+ (1,0) [0|3] ""  DCDC
 SG_ M2D_CMD1_DCDCLVoffControl_01 : 60|1@1+ (1,0) [0|1] ""  DCDC
 SG_ M2D_CMD1_Reserved4_01 : 61|2@1+ (1,0) [0|3] ""  DCDC

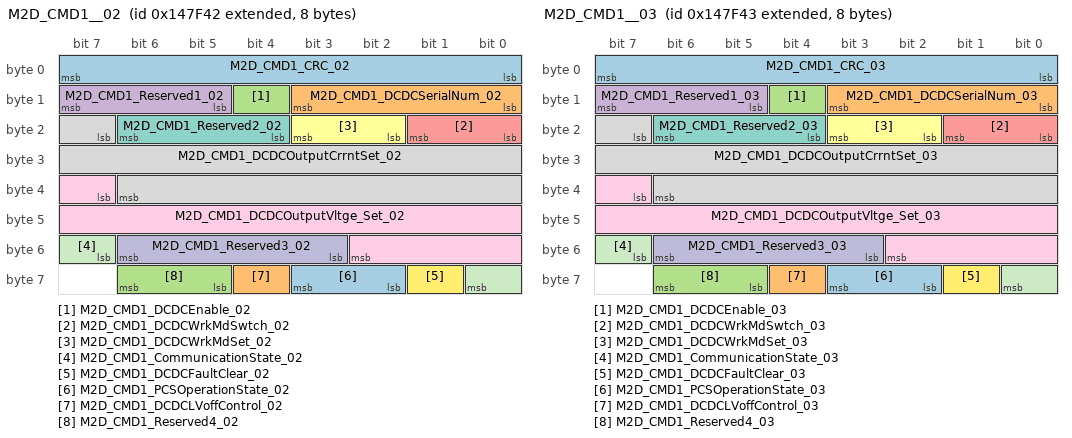
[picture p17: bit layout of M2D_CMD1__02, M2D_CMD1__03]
BO_ 2148826946 M2D_CMD1__02: 8 MBMU
 SG_ M2D_CMD1_CRC_02 : 0|8@1+ (1,0) [0|255] ""  DCDC
 SG_ M2D_CMD1_DCDCSerialNum_02 : 8|4@1+ (1,0) [0|15] ""  DCDC
 SG_ M2D_CMD1_DCDCEnable_02 : 12|1@1+ (1,0) [0|1] ""  DCDC
 SG_ M2D_CMD1_Reserved1_02 : 13|3@1+ (1,0) [0|7] ""  DCDC
 SG_ M2D_CMD1_DCDCWrkMdSwtch_02 : 16|2@1+ (1,0) [0|3] ""  DCDC
 SG_ M2D_CMD1_DCDCWrkMdSet_02 : 18|2@1+ (1,0) [0|3] ""  DCDC
 SG_ M2D_CMD1_Reserved2_02 : 20|3@1+ (1,0) [0|7] ""  DCDC
 SG_ M2D_CMD1_DCDCOutputCrrntSet_02 : 23|16@1+ (0.05,-2000) [-2000|1276.75] "A"  DCDC
 SG_ M2D_CMD1_DCDCOutputVltge_Set_02 : 39|12@1+ (0.1,-200) [-200|209.5] "V"  DCDC
 SG_ M2D_CMD1_Reserved3_02 : 51|4@1+ (1,0) [0|15] ""  DCDC
 SG_ M2D_CMD1_CommunicationState_02 : 55|2@1+ (1,0) [0|3] ""  DCDC
 SG_ M2D_CMD1_DCDCFaultClear_02 : 57|1@1+ (1,0) [0|1] ""  DCDC
 SG_ M2D_CMD1_PCSOperationState_02 : 58|2@1+ (1,0) [0|3] ""  DCDC
 SG_ M2D_CMD1_DCDCLVoffControl_02 : 60|1@1+ (1,0) [0|1] ""  DCDC
 SG_ M2D_CMD1_Reserved4_02 : 61|2@1+ (1,0) [0|3] ""  DCDC

BO_ 2148826947 M2D_CMD1__03: 8 MBMU
 SG_ M2D_CMD1_CRC_03 : 0|8@1+ (1,0) [0|255] ""  DCDC
 SG_ M2D_CMD1_DCDCSerialNum_03 : 8|4@1+ (1,0) [0|15] ""  DCDC
 SG_ M2D_CMD1_DCDCEnable_03 : 12|1@1+ (1,0) [0|1] ""  DCDC
 SG_ M2D_CMD1_Reserved1_03 : 13|3@1+ (1,0) [0|7] ""  DCDC
 SG_ M2D_CMD1_DCDCWrkMdSwtch_03 : 16|2@1+ (1,0) [0|3] ""  DCDC
 SG_ M2D_CMD1_DCDCWrkMdSet_03 : 18|2@1+ (1,0) [0|3] ""  DCDC
 SG_ M2D_CMD1_Reserved2_03 : 20|3@1+ (1,0) [0|7] ""  DCDC
 SG_ M2D_CMD1_DCDCOutputCrrntSet_03 : 23|16@1+ (0.05,-2000) [-2000|1276.75] "A"  DCDC
 SG_ M2D_CMD1_DCDCOutputVltge_Set_03 : 39|12@1+ (0.1,-200) [-200|209.5] "V"  DCDC
 SG_ M2D_CMD1_Reserved3_03 : 51|4@1+ (1,0) [0|15] ""  DCDC
 SG_ M2D_CMD1_CommunicationState_03 : 55|2@1+ (1,0) [0|3] ""  DCDC
 SG_ M2D_CMD1_DCDCFaultClear_03 : 57|1@1+ (1,0) [0|1] ""  DCDC
 SG_ M2D_CMD1_PCSOperationState_03 : 58|2@1+ (1,0) [0|3] ""  DCDC
 SG_ M2D_CMD1_DCDCLVoffControl_03 : 60|1@1+ (1,0) [0|1] ""  DCDC
 SG_ M2D_CMD1_Reserved4_03 : 61|2@1+ (1,0) [0|3] ""  DCDC

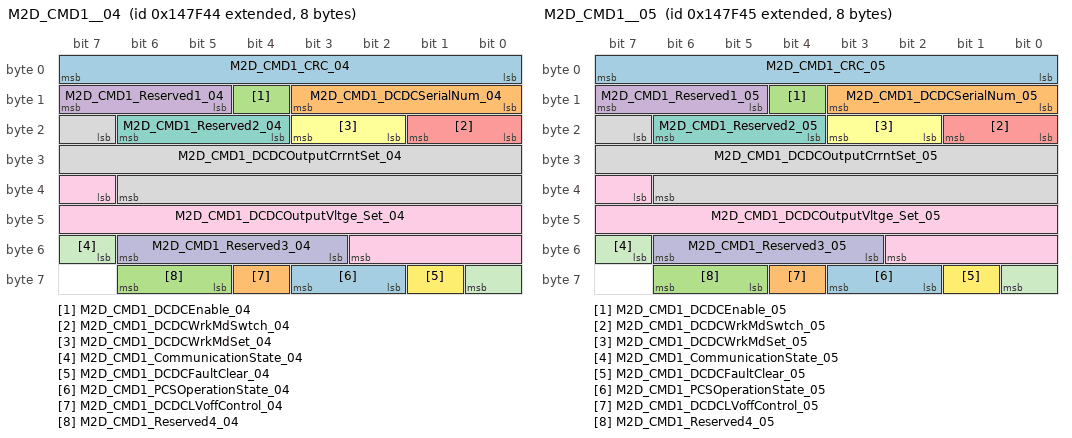
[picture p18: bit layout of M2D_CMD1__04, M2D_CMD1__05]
BO_ 2148826948 M2D_CMD1__04: 8 MBMU
 SG_ M2D_CMD1_CRC_04 : 0|8@1+ (1,0) [0|255] ""  DCDC
 SG_ M2D_CMD1_DCDCSerialNum_04 : 8|4@1+ (1,0) [0|15] ""  DCDC
 SG_ M2D_CMD1_DCDCEnable_04 : 12|1@1+ (1,0) [0|1] ""  DCDC
 SG_ M2D_CMD1_Reserved1_04 : 13|3@1+ (1,0) [0|7] ""  DCDC
 SG_ M2D_CMD1_DCDCWrkMdSwtch_04 : 16|2@1+ (1,0) [0|3] ""  DCDC
 SG_ M2D_CMD1_DCDCWrkMdSet_04 : 18|2@1+ (1,0) [0|3] ""  DCDC
 SG_ M2D_CMD1_Reserved2_04 : 20|3@1+ (1,0) [0|7] ""  DCDC
 SG_ M2D_CMD1_DCDCOutputCrrntSet_04 : 23|16@1+ (0.05,-2000) [-2000|1276.75] "A"  DCDC
 SG_ M2D_CMD1_DCDCOutputVltge_Set_04 : 39|12@1+ (0.1,-200) [-200|209.5] "V"  DCDC
 SG_ M2D_CMD1_Reserved3_04 : 51|4@1+ (1,0) [0|15] ""  DCDC
 SG_ M2D_CMD1_CommunicationState_04 : 55|2@1+ (1,0) [0|3] ""  DCDC
 SG_ M2D_CMD1_DCDCFaultClear_04 : 57|1@1+ (1,0) [0|1] ""  DCDC
 SG_ M2D_CMD1_PCSOperationState_04 : 58|2@1+ (1,0) [0|3] ""  DCDC
 SG_ M2D_CMD1_DCDCLVoffControl_04 : 60|1@1+ (1,0) [0|1] ""  DCDC
 SG_ M2D_CMD1_Reserved4_04 : 61|2@1+ (1,0) [0|3] ""  DCDC

BO_ 2148826949 M2D_CMD1__05: 8 MBMU
 SG_ M2D_CMD1_CRC_05 : 0|8@1+ (1,0) [0|255] ""  DCDC
 SG_ M2D_CMD1_DCDCSerialNum_05 : 8|4@1+ (1,0) [0|15] ""  DCDC
 SG_ M2D_CMD1_DCDCEnable_05 : 12|1@1+ (1,0) [0|1] ""  DCDC
 SG_ M2D_CMD1_Reserved1_05 : 13|3@1+ (1,0) [0|7] ""  DCDC
 SG_ M2D_CMD1_DCDCWrkMdSwtch_05 : 16|2@1+ (1,0) [0|3] ""  DCDC
 SG_ M2D_CMD1_DCDCWrkMdSet_05 : 18|2@1+ (1,0) [0|3] ""  DCDC
 SG_ M2D_CMD1_Reserved2_05 : 20|3@1+ (1,0) [0|7] ""  DCDC
 SG_ M2D_CMD1_DCDCOutputCrrntSet_05 : 23|16@1+ (0.05,-2000) [-2000|1276.75] "A"  DCDC
 SG_ M2D_CMD1_DCDCOutputVltge_Set_05 : 39|12@1+ (0.1,-200) [-200|209.5] "V"  DCDC
 SG_ M2D_CMD1_Reserved3_05 : 51|4@1+ (1,0) [0|15] ""  DCDC
 SG_ M2D_CMD1_CommunicationState_05 : 55|2@1+ (1,0) [0|3] ""  DCDC
 SG_ M2D_CMD1_DCDCFaultClear_05 : 57|1@1+ (1,0) [0|1] ""  DCDC
 SG_ M2D_CMD1_PCSOperationState_05 : 58|2@1+ (1,0) [0|3] ""  DCDC
 SG_ M2D_CMD1_DCDCLVoffControl_05 : 60|1@1+ (1,0) [0|1] ""  DCDC
 SG_ M2D_CMD1_Reserved4_05 : 61|2@1+ (1,0) [0|3] ""  DCDC

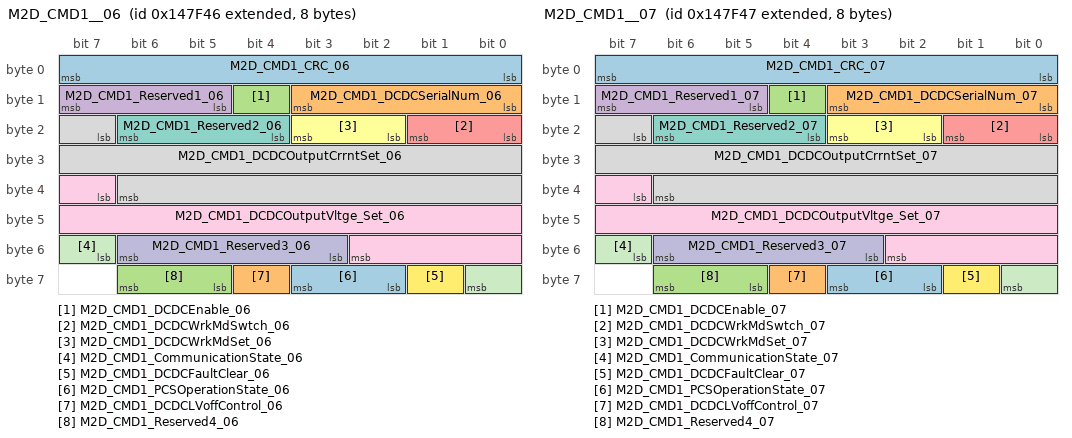
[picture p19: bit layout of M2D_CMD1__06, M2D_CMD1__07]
BO_ 2148826950 M2D_CMD1__06: 8 MBMU
 SG_ M2D_CMD1_CRC_06 : 0|8@1+ (1,0) [0|255] ""  DCDC
 SG_ M2D_CMD1_DCDCSerialNum_06 : 8|4@1+ (1,0) [0|15] ""  DCDC
 SG_ M2D_CMD1_DCDCEnable_06 : 12|1@1+ (1,0) [0|1] ""  DCDC
 SG_ M2D_CMD1_Reserved1_06 : 13|3@1+ (1,0) [0|7] ""  DCDC
 SG_ M2D_CMD1_DCDCWrkMdSwtch_06 : 16|2@1+ (1,0) [0|3] ""  DCDC
 SG_ M2D_CMD1_DCDCWrkMdSet_06 : 18|2@1+ (1,0) [0|3] ""  DCDC
 SG_ M2D_CMD1_Reserved2_06 : 20|3@1+ (1,0) [0|7] ""  DCDC
 SG_ M2D_CMD1_DCDCOutputCrrntSet_06 : 23|16@1+ (0.05,-2000) [-2000|1276.75] "A"  DCDC
 SG_ M2D_CMD1_DCDCOutputVltge_Set_06 : 39|12@1+ (0.1,-200) [-200|209.5] "V"  DCDC
 SG_ M2D_CMD1_Reserved3_06 : 51|4@1+ (1,0) [0|15] ""  DCDC
 SG_ M2D_CMD1_CommunicationState_06 : 55|2@1+ (1,0) [0|3] ""  DCDC
 SG_ M2D_CMD1_DCDCFaultClear_06 : 57|1@1+ (1,0) [0|1] ""  DCDC
 SG_ M2D_CMD1_PCSOperationState_06 : 58|2@1+ (1,0) [0|3] ""  DCDC
 SG_ M2D_CMD1_DCDCLVoffControl_06 : 60|1@1+ (1,0) [0|1] ""  DCDC
 SG_ M2D_CMD1_Reserved4_06 : 61|2@1+ (1,0) [0|3] ""  DCDC

BO_ 2148826951 M2D_CMD1__07: 8 MBMU
 SG_ M2D_CMD1_CRC_07 : 0|8@1+ (1,0) [0|255] ""  DCDC
 SG_ M2D_CMD1_DCDCSerialNum_07 : 8|4@1+ (1,0) [0|15] ""  DCDC
 SG_ M2D_CMD1_DCDCEnable_07 : 12|1@1+ (1,0) [0|1] ""  DCDC
 SG_ M2D_CMD1_Reserved1_07 : 13|3@1+ (1,0) [0|7] ""  DCDC
 SG_ M2D_CMD1_DCDCWrkMdSwtch_07 : 16|2@1+ (1,0) [0|3] ""  DCDC
 SG_ M2D_CMD1_DCDCWrkMdSet_07 : 18|2@1+ (1,0) [0|3] ""  DCDC
 SG_ M2D_CMD1_Reserved2_07 : 20|3@1+ (1,0) [0|7] ""  DCDC
 SG_ M2D_CMD1_DCDCOutputCrrntSet_07 : 23|16@1+ (0.05,-2000) [-2000|1276.75] "A"  DCDC
 SG_ M2D_CMD1_DCDCOutputVltge_Set_07 : 39|12@1+ (0.1,-200) [-200|209.5] "V"  DCDC
 SG_ M2D_CMD1_Reserved3_07 : 51|4@1+ (1,0) [0|15] ""  DCDC
 SG_ M2D_CMD1_CommunicationState_07 : 55|2@1+ (1,0) [0|3] ""  DCDC
 SG_ M2D_CMD1_DCDCFaultClear_07 : 57|1@1+ (1,0) [0|1] ""  DCDC
 SG_ M2D_CMD1_PCSOperationState_07 : 58|2@1+ (1,0) [0|3] ""  DCDC
 SG_ M2D_CMD1_DCDCLVoffControl_07 : 60|1@1+ (1,0) [0|1] ""  DCDC
 SG_ M2D_CMD1_Reserved4_07 : 61|2@1+ (1,0) [0|3] ""  DCDC

CM_ SG_ 2416242337 M2P_Cfg3_HW_Ver_Byte1_17 "MBMU硬件版本号最低字节Byte1对应ASCII码";
CM_ SG_ 2416242337 M2P_Cfg3_HW_Ver_Byte2_17 "MBMU硬件版本号Byte2对应ASCII码";
CM_ SG_ 2416242337 M2P_Cfg3_HW_Ver_Byte3_17 "MBMU硬件版本号Byte3对应ASCII码";
CM_ SG_ 2416242337 M2P_Cfg3_HW_Ver_Byte4_17 "MBMU硬件版本号Byte4对应ASCII码";
CM_ SG_ 2416242337 M2P_Cfg3_HW_Ver_Byte5_17 "MBMU硬件版本号Byte5对应ASCII码";
CM_ SG_ 2416242337 M2P_Cfg3_HW_Ver_Byte6_17 "MBMU硬件版本号Byte6对应ASCII码";
CM_ SG_ 2416242337 M2P_Cfg3_HW_Ver_Byte7_17 "MBMU硬件版本号Byte7对应ASCII码";
CM_ SG_ 2416242337 M2P_Cfg3_HW_Ver_Byte8_17 "MBMU硬件版本号Byte8对应ASCII码";
CM_ SG_ 2416242338 M2P_Cfg3_HW_Ver_Byte1_18 "MBMU硬件版本号最低字节Byte1对应ASCII码";
CM_ SG_ 2416242338 M2P_Cfg3_HW_Ver_Byte2_18 "MBMU硬件版本号Byte2对应ASCII码";
CM_ SG_ 2416242338 M2P_Cfg3_HW_Ver_Byte3_18 "MBMU硬件版本号Byte3对应ASCII码";
CM_ SG_ 2416242338 M2P_Cfg3_HW_Ver_Byte4_18 "MBMU硬件版本号Byte4对应ASCII码";
CM_ SG_ 2416242338 M2P_Cfg3_HW_Ver_Byte5_18 "MBMU硬件版本号Byte5对应ASCII码";
CM_ SG_ 2416242338 M2P_Cfg3_HW_Ver_Byte6_18 "MBMU硬件版本号Byte6对应ASCII码";
CM_ SG_ 2416242338 M2P_Cfg3_HW_Ver_Byte7_18 "MBMU硬件版本号Byte7对应ASCII码";
CM_ SG_ 2416242338 M2P_Cfg3_HW_Ver_Byte8_18 "MBMU硬件版本号Byte8对应ASCII码";
CM_ SG_ 2416242339 M2P_Cfg3_HW_Ver_Byte1_19 "MBMU硬件版本号最低字节Byte1对应ASCII码";
CM_ SG_ 2416242339 M2P_Cfg3_HW_Ver_Byte2_19 "MBMU硬件版本号Byte2对应ASCII码";
CM_ SG_ 2416242339 M2P_Cfg3_HW_Ver_Byte3_19 "MBMU硬件版本号Byte3对应ASCII码";
CM_ SG_ 2416242339 M2P_Cfg3_HW_Ver_Byte4_19 "MBMU硬件版本号Byte4对应ASCII码";
CM_ SG_ 2416242339 M2P_Cfg3_HW_Ver_Byte5_19 "MBMU硬件版本号Byte5对应ASCII码";
CM_ SG_ 2416242339 M2P_Cfg3_HW_Ver_Byte6_19 "MBMU硬件版本号Byte6对应ASCII码";
CM_ SG_ 2416242339 M2P_Cfg3_HW_Ver_Byte7_19 "MBMU硬件版本号Byte7对应ASCII码";
CM_ SG_ 2416242339 M2P_Cfg3_HW_Ver_Byte8_19 "MBMU硬件版本号Byte8对应ASCII码";
CM_ SG_ 2416242340 M2P_Cfg3_HW_Ver_Byte1_20 "MBMU硬件版本号最低字节Byte1对应ASCII码";
CM_ SG_ 2416242340 M2P_Cfg3_HW_Ver_Byte2_20 "MBMU硬件版本号Byte2对应ASCII码";
CM_ SG_ 2416242340 M2P_Cfg3_HW_Ver_Byte3_20 "MBMU硬件版本号Byte3对应ASCII码";
CM_ SG_ 2416242340 M2P_Cfg3_HW_Ver_Byte4_20 "MBMU硬件版本号Byte4对应ASCII码";
CM_ SG_ 2416242340 M2P_Cfg3_HW_Ver_Byte5_20 "MBMU硬件版本号Byte5对应ASCII码";
CM_ SG_ 2416242340 M2P_Cfg3_HW_Ver_Byte6_20 "MBMU硬件版本号Byte6对应ASCII码";
CM_ SG_ 2416242340 M2P_Cfg3_HW_Ver_Byte7_20 "MBMU硬件版本号Byte7对应ASCII码";
CM_ SG_ 2416242340 M2P_Cfg3_HW_Ver_Byte8_20 "MBMU硬件版本号Byte8对应ASCII码";
CM_ SG_ 2416242341 M2P_Cfg3_HW_Ver_Byte1_21 "MBMU硬件版本号最低字节Byte1对应ASCII码";
CM_ SG_ 2416242341 M2P_Cfg3_HW_Ver_Byte2_21 "MBMU硬件版本号Byte2对应ASCII码";
CM_ SG_ 2416242341 M2P_Cfg3_HW_Ver_Byte3_21 "MBMU硬件版本号Byte3对应ASCII码";
CM_ SG_ 2416242341 M2P_Cfg3_HW_Ver_Byte4_21 "MBMU硬件版本号Byte4对应ASCII码";
CM_ SG_ 2416242341 M2P_Cfg3_HW_Ver_Byte5_21 "MBMU硬件版本号Byte5对应ASCII码";
CM_ SG_ 2416242341 M2P_Cfg3_HW_Ver_Byte6_21 "MBMU硬件版本号Byte6对应ASCII码";
CM_ SG_ 2416242341 M2P_Cfg3_HW_Ver_Byte7_21 "MBMU硬件版本号Byte7对应ASCII码";
CM_ SG_ 2416242341 M2P_Cfg3_HW_Ver_Byte8_21 "MBMU硬件版本号Byte8对应ASCII码";
CM_ SG_ 2416242342 M2P_Cfg3_HW_Ver_Byte1_22 "MBMU硬件版本号最低字节Byte1对应ASCII码";
CM_ SG_ 2416242342 M2P_Cfg3_HW_Ver_Byte2_22 "MBMU硬件版本号Byte2对应ASCII码";
CM_ SG_ 2416242342 M2P_Cfg3_HW_Ver_Byte3_22 "MBMU硬件版本号Byte3对应ASCII码";
CM_ SG_ 2416242342 M2P_Cfg3_HW_Ver_Byte4_22 "MBMU硬件版本号Byte4对应ASCII码";
CM_ SG_ 2416242342 M2P_Cfg3_HW_Ver_Byte5_22 "MBMU硬件版本号Byte5对应ASCII码";
CM_ SG_ 2416242342 M2P_Cfg3_HW_Ver_Byte6_22 "MBMU硬件版本号Byte6对应ASCII码";
CM_ SG_ 2416242342 M2P_Cfg3_HW_Ver_Byte7_22 "MBMU硬件版本号Byte7对应ASCII码";
CM_ SG_ 2416242342 M2P_Cfg3_HW_Ver_Byte8_22 "MBMU硬件版本号Byte8对应ASCII码";
CM_ SG_ 2416242343 M2P_Cfg3_HW_Ver_Byte1_23 "MBMU硬件版本号最低字节Byte1对应ASCII码";
CM_ SG_ 2416242343 M2P_Cfg3_HW_Ver_Byte2_23 "MBMU硬件版本号Byte2对应ASCII码";
CM_ SG_ 2416242343 M2P_Cfg3_HW_Ver_Byte3_23 "MBMU硬件版本号Byte3对应ASCII码";
CM_ SG_ 2416242343 M2P_Cfg3_HW_Ver_Byte4_23 "MBMU硬件版本号Byte4对应ASCII码";
CM_ SG_ 2416242343 M2P_Cfg3_HW_Ver_Byte5_23 "MBMU硬件版本号Byte5对应ASCII码";
CM_ SG_ 2416242343 M2P_Cfg3_HW_Ver_Byte6_23 "MBMU硬件版本号Byte6对应ASCII码";
CM_ SG_ 2416242343 M2P_Cfg3_HW_Ver_Byte7_23 "MBMU硬件版本号Byte7对应ASCII码";
CM_ SG_ 2416242343 M2P_Cfg3_HW_Ver_Byte8_23 "MBMU硬件版本号Byte8对应ASCII码";
CM_ SG_ 2416242344 M2P_Cfg3_HW_Ver_Byte1_24 "MBMU硬件版本号最低字节Byte1对应ASCII码";
CM_ SG_ 2416242344 M2P_Cfg3_HW_Ver_Byte2_24 "MBMU硬件版本号Byte2对应ASCII码";
CM_ SG_ 2416242344 M2P_Cfg3_HW_Ver_Byte3_24 "MBMU硬件版本号Byte3对应ASCII码";
CM_ SG_ 2416242344 M2P_Cfg3_HW_Ver_Byte4_24 "MBMU硬件版本号Byte4对应ASCII码";
CM_ SG_ 2416242344 M2P_Cfg3_HW_Ver_Byte5_24 "MBMU硬件版本号Byte5对应ASCII码";
CM_ SG_ 2416242344 M2P_Cfg3_HW_Ver_Byte6_24 "MBMU硬件版本号Byte6对应ASCII码";
CM_ SG_ 2416242344 M2P_Cfg3_HW_Ver_Byte7_24 "MBMU硬件版本号Byte7对应ASCII码";
CM_ SG_ 2416242344 M2P_Cfg3_HW_Ver_Byte8_24 "MBMU硬件版本号Byte8对应ASCII码";
CM_ SG_ 2416242345 M2P_Cfg3_HW_Ver_Byte1_25 "MBMU硬件版本号最低字节Byte1对应ASCII码";
CM_ SG_ 2416242345 M2P_Cfg3_HW_Ver_Byte2_25 "MBMU硬件版本号Byte2对应ASCII码";
CM_ SG_ 2416242345 M2P_Cfg3_HW_Ver_Byte3_25 "MBMU硬件版本号Byte3对应ASCII码";
CM_ SG_ 2416242345 M2P_Cfg3_HW_Ver_Byte4_25 "MBMU硬件版本号Byte4对应ASCII码";
CM_ SG_ 2416242345 M2P_Cfg3_HW_Ver_Byte5_25 "MBMU硬件版本号Byte5对应ASCII码";
CM_ SG_ 2416242345 M2P_Cfg3_HW_Ver_Byte6_25 "MBMU硬件版本号Byte6对应ASCII码";
CM_ SG_ 2416242345 M2P_Cfg3_HW_Ver_Byte7_25 "MBMU硬件版本号Byte7对应ASCII码";
CM_ SG_ 2416242345 M2P_Cfg3_HW_Ver_Byte8_25 "MBMU硬件版本号Byte8对应ASCII码";
CM_ SG_ 2416242346 M2P_Cfg3_HW_Ver_Byte1_26 "MBMU硬件版本号最低字节Byte1对应ASCII码";
CM_ SG_ 2416242346 M2P_Cfg3_HW_Ver_Byte2_26 "MBMU硬件版本号Byte2对应ASCII码";
CM_ SG_ 2416242346 M2P_Cfg3_HW_Ver_Byte3_26 "MBMU硬件版本号Byte3对应ASCII码";
CM_ SG_ 2416242346 M2P_Cfg3_HW_Ver_Byte4_26 "MBMU硬件版本号Byte4对应ASCII码";
CM_ SG_ 2416242346 M2P_Cfg3_HW_Ver_Byte5_26 "MBMU硬件版本号Byte5对应ASCII码";
CM_ SG_ 2416242346 M2P_Cfg3_HW_Ver_Byte6_26 "MBMU硬件版本号Byte6对应ASCII码";
CM_ SG_ 2416242346 M2P_Cfg3_HW_Ver_Byte7_26 "MBMU硬件版本号Byte7对应ASCII码";
CM_ SG_ 2416242346 M2P_Cfg3_HW_Ver_Byte8_26 "MBMU硬件版本号Byte8对应ASCII码";
CM_ SG_ 2416242347 M2P_Cfg3_HW_Ver_Byte1_27 "MBMU硬件版本号最低字节Byte1对应ASCII码";
CM_ SG_ 2416242347 M2P_Cfg3_HW_Ver_Byte2_27 "MBMU硬件版本号Byte2对应ASCII码";
CM_ SG_ 2416242347 M2P_Cfg3_HW_Ver_Byte3_27 "MBMU硬件版本号Byte3对应ASCII码";
CM_ SG_ 2416242347 M2P_Cfg3_HW_Ver_Byte4_27 "MBMU硬件版本号Byte4对应ASCII码";
CM_ SG_ 2416242347 M2P_Cfg3_HW_Ver_Byte5_27 "MBMU硬件版本号Byte5对应ASCII码";
CM_ SG_ 2416242347 M2P_Cfg3_HW_Ver_Byte6_27 "MBMU硬件版本号Byte6对应ASCII码";
CM_ SG_ 2416242347 M2P_Cfg3_HW_Ver_Byte7_27 "MBMU硬件版本号Byte7对应ASCII码";
CM_ SG_ 2416242347 M2P_Cfg3_HW_Ver_Byte8_27 "MBMU硬件版本号Byte8对应ASCII码";
CM_ SG_ 2416242348 M2P_Cfg3_HW_Ver_Byte1_28 "MBMU硬件版本号最低字节Byte1对应ASCII码";
CM_ SG_ 2416242348 M2P_Cfg3_HW_Ver_Byte2_28 "MBMU硬件版本号Byte2对应ASCII码";
CM_ SG_ 2416242348 M2P_Cfg3_HW_Ver_Byte3_28 "MBMU硬件版本号Byte3对应ASCII码";
CM_ SG_ 2416242348 M2P_Cfg3_HW_Ver_Byte4_28 "MBMU硬件版本号Byte4对应ASCII码";
CM_ SG_ 2416242348 M2P_Cfg3_HW_Ver_Byte5_28 "MBMU硬件版本号Byte5对应ASCII码";
CM_ SG_ 2416242348 M2P_Cfg3_HW_Ver_Byte6_28 "MBMU硬件版本号Byte6对应ASCII码";
CM_ SG_ 2416242348 M2P_Cfg3_HW_Ver_Byte7_28 "MBMU硬件版本号Byte7对应ASCII码";
CM_ SG_ 2416242348 M2P_Cfg3_HW_Ver_Byte8_28 "MBMU硬件版本号Byte8对应ASCII码";
CM_ SG_ 2416242349 M2P_Cfg3_HW_Ver_Byte1_29 "MBMU硬件版本号最低字节Byte1对应ASCII码";
CM_ SG_ 2416242349 M2P_Cfg3_HW_Ver_Byte2_29 "MBMU硬件版本号Byte2对应ASCII码";
CM_ SG_ 2416242349 M2P_Cfg3_HW_Ver_Byte3_29 "MBMU硬件版本号Byte3对应ASCII码";
CM_ SG_ 2416242349 M2P_Cfg3_HW_Ver_Byte4_29 "MBMU硬件版本号Byte4对应ASCII码";
CM_ SG_ 2416242349 M2P_Cfg3_HW_Ver_Byte5_29 "MBMU硬件版本号Byte5对应ASCII码";
CM_ SG_ 2416242349 M2P_Cfg3_HW_Ver_Byte6_29 "MBMU硬件版本号Byte6对应ASCII码";
CM_ SG_ 2416242349 M2P_Cfg3_HW_Ver_Byte7_29 "MBMU硬件版本号Byte7对应ASCII码";
CM_ SG_ 2416242349 M2P_Cfg3_HW_Ver_Byte8_29 "MBMU硬件版本号Byte8对应ASCII码";
CM_ SG_ 2416242350 M2P_Cfg3_HW_Ver_Byte1_30 "MBMU硬件版本号最低字节Byte1对应ASCII码";
CM_ SG_ 2416242350 M2P_Cfg3_HW_Ver_Byte2_30 "MBMU硬件版本号Byte2对应ASCII码";
CM_ SG_ 2416242350 M2P_Cfg3_HW_Ver_Byte3_30 "MBMU硬件版本号Byte3对应ASCII码";
CM_ SG_ 2416242350 M2P_Cfg3_HW_Ver_Byte4_30 "MBMU硬件版本号Byte4对应ASCII码";
CM_ SG_ 2416242350 M2P_Cfg3_HW_Ver_Byte5_30 "MBMU硬件版本号Byte5对应ASCII码";
CM_ SG_ 2416242350 M2P_Cfg3_HW_Ver_Byte6_30 "MBMU硬件版本号Byte6对应ASCII码";
CM_ SG_ 2416242350 M2P_Cfg3_HW_Ver_Byte7_30 "MBMU硬件版本号Byte7对应ASCII码";
CM_ SG_ 2416242350 M2P_Cfg3_HW_Ver_Byte8_30 "MBMU硬件版本号Byte8对应ASCII码";
CM_ SG_ 2416242351 M2P_Cfg3_HW_Ver_Byte1_31 "MBMU硬件版本号最低字节Byte1对应ASCII码";
CM_ SG_ 2416242351 M2P_Cfg3_HW_Ver_Byte2_31 "MBMU硬件版本号Byte2对应ASCII码";
CM_ SG_ 2416242351 M2P_Cfg3_HW_Ver_Byte3_31 "MBMU硬件版本号Byte3对应ASCII码";
CM_ SG_ 2416242351 M2P_Cfg3_HW_Ver_Byte4_31 "MBMU硬件版本号Byte4对应ASCII码";
CM_ SG_ 2416242351 M2P_Cfg3_HW_Ver_Byte5_31 "MBMU硬件版本号Byte5对应ASCII码";
CM_ SG_ 2416242351 M2P_Cfg3_HW_Ver_Byte6_31 "MBMU硬件版本号Byte6对应ASCII码";
CM_ SG_ 2416242351 M2P_Cfg3_HW_Ver_Byte7_31 "MBMU硬件版本号Byte7对应ASCII码";
CM_ SG_ 2416242351 M2P_Cfg3_HW_Ver_Byte8_31 "MBMU硬件版本号Byte8对应ASCII码";
CM_ SG_ 2416307857 M2P_Cfg4_HW_Ver_Byte9_01 "MBMU硬件版本号Byte9对应ASCII码";
CM_ SG_ 2416307857 M2P_Cfg4_HW_Ver_Byte10_01 "MBMU硬件版本号Byte10对应ASCII码";
CM_ SG_ 2416307857 M2P_Cfg4_HW_Ver_Byte11_01 "MBMU硬件版本号Byte11对应ASCII码";
CM_ SG_ 2416307857 M2P_Cfg4_HW_Ver_Byte12_01 "MBMU硬件版本号Byte12对应ASCII码";
CM_ SG_ 2416307857 M2P_Cfg4_HW_Ver_Byte13_01 "MBMU硬件版本号Byte13对应ASCII码";
CM_ SG_ 2416307857 M2P_Cfg4_HW_Ver_Byte14_01 "MBMU硬件版本号Byte14对应ASCII码";
CM_ SG_ 2416307857 M2P_Cfg4_HW_Ver_Byte15_01 "MBMU硬件版本号Byte15对应ASCII码";
CM_ SG_ 2416307857 M2P_Cfg4_HW_Ver_Byte16_01 "MBMU硬件版本号最高字节Byte16对应ASCII码";
CM_ SG_ 2416307858 M2P_Cfg4_HW_Ver_Byte9_02 "MBMU硬件版本号Byte9对应ASCII码";
CM_ SG_ 2416307858 M2P_Cfg4_HW_Ver_Byte10_02 "MBMU硬件版本号Byte10对应ASCII码";
CM_ SG_ 2416307858 M2P_Cfg4_HW_Ver_Byte11_02 "MBMU硬件版本号Byte11对应ASCII码";
CM_ SG_ 2416307858 M2P_Cfg4_HW_Ver_Byte12_02 "MBMU硬件版本号Byte12对应ASCII码";
CM_ SG_ 2416307858 M2P_Cfg4_HW_Ver_Byte13_02 "MBMU硬件版本号Byte13对应ASCII码";
CM_ SG_ 2416307858 M2P_Cfg4_HW_Ver_Byte14_02 "MBMU硬件版本号Byte14对应ASCII码";
CM_ SG_ 2416307858 M2P_Cfg4_HW_Ver_Byte15_02 "MBMU硬件版本号Byte15对应ASCII码";
CM_ SG_ 2416307858 M2P_Cfg4_HW_Ver_Byte16_02 "MBMU硬件版本号最高字节Byte16对应ASCII码";
CM_ SG_ 2416307859 M2P_Cfg4_HW_Ver_Byte9_03 "MBMU硬件版本号Byte9对应ASCII码";
CM_ SG_ 2416307859 M2P_Cfg4_HW_Ver_Byte10_03 "MBMU硬件版本号Byte10对应ASCII码";
CM_ SG_ 2416307859 M2P_Cfg4_HW_Ver_Byte11_03 "MBMU硬件版本号Byte11对应ASCII码";
CM_ SG_ 2416307859 M2P_Cfg4_HW_Ver_Byte12_03 "MBMU硬件版本号Byte12对应ASCII码";
CM_ SG_ 2416307859 M2P_Cfg4_HW_Ver_Byte13_03 "MBMU硬件版本号Byte13对应ASCII码";
CM_ SG_ 2416307859 M2P_Cfg4_HW_Ver_Byte14_03 "MBMU硬件版本号Byte14对应ASCII码";
CM_ SG_ 2416307859 M2P_Cfg4_HW_Ver_Byte15_03 "MBMU硬件版本号Byte15对应ASCII码";
CM_ SG_ 2416307859 M2P_Cfg4_HW_Ver_Byte16_03 "MBMU硬件版本号最高字节Byte16对应ASCII码";
CM_ SG_ 2416307860 M2P_Cfg4_HW_Ver_Byte9_04 "MBMU硬件版本号Byte9对应ASCII码";
CM_ SG_ 2416307860 M2P_Cfg4_HW_Ver_Byte10_04 "MBMU硬件版本号Byte10对应ASCII码";
CM_ SG_ 2416307860 M2P_Cfg4_HW_Ver_Byte11_04 "MBMU硬件版本号Byte11对应ASCII码";
CM_ SG_ 2416307860 M2P_Cfg4_HW_Ver_Byte12_04 "MBMU硬件版本号Byte12对应ASCII码";
CM_ SG_ 2416307860 M2P_Cfg4_HW_Ver_Byte13_04 "MBMU硬件版本号Byte13对应ASCII码";
CM_ SG_ 2416307860 M2P_Cfg4_HW_Ver_Byte14_04 "MBMU硬件版本号Byte14对应ASCII码";
CM_ SG_ 2416307860 M2P_Cfg4_HW_Ver_Byte15_04 "MBMU硬件版本号Byte15对应ASCII码";
CM_ SG_ 2416307860 M2P_Cfg4_HW_Ver_Byte16_04 "MBMU硬件版本号最高字节Byte16对应ASCII码";
CM_ SG_ 2416307861 M2P_Cfg4_HW_Ver_Byte9_05 "MBMU硬件版本号Byte9对应ASCII码";
CM_ SG_ 2416307861 M2P_Cfg4_HW_Ver_Byte10_05 "MBMU硬件版本号Byte10对应ASCII码";
CM_ SG_ 2416307861 M2P_Cfg4_HW_Ver_Byte11_05 "MBMU硬件版本号Byte11对应ASCII码";
CM_ SG_ 2416307861 M2P_Cfg4_HW_Ver_Byte12_05 "MBMU硬件版本号Byte12对应ASCII码";
CM_ SG_ 2416307861 M2P_Cfg4_HW_Ver_Byte13_05 "MBMU硬件版本号Byte13对应ASCII码";
CM_ SG_ 2416307861 M2P_Cfg4_HW_Ver_Byte14_05 "MBMU硬件版本号Byte14对应ASCII码";
CM_ SG_ 2416307861 M2P_Cfg4_HW_Ver_Byte15_05 "MBMU硬件版本号Byte15对应ASCII码";
CM_ SG_ 2416307861 M2P_Cfg4_HW_Ver_Byte16_05 "MBMU硬件版本号最高字节Byte16对应ASCII码";
CM_ SG_ 2416307862 M2P_Cfg4_HW_Ver_Byte9_06 "MBMU硬件版本号Byte9对应ASCII码";
CM_ SG_ 2416307862 M2P_Cfg4_HW_Ver_Byte10_06 "MBMU硬件版本号Byte10对应ASCII码";
CM_ SG_ 2416307862 M2P_Cfg4_HW_Ver_Byte11_06 "MBMU硬件版本号Byte11对应ASCII码";
CM_ SG_ 2416307862 M2P_Cfg4_HW_Ver_Byte12_06 "MBMU硬件版本号Byte12对应ASCII码";
CM_ SG_ 2416307862 M2P_Cfg4_HW_Ver_Byte13_06 "MBMU硬件版本号Byte13对应ASCII码";
CM_ SG_ 2416307862 M2P_Cfg4_HW_Ver_Byte14_06 "MBMU硬件版本号Byte14对应ASCII码";
CM_ SG_ 2416307862 M2P_Cfg4_HW_Ver_Byte15_06 "MBMU硬件版本号Byte15对应ASCII码";
CM_ SG_ 2416307862 M2P_Cfg4_HW_Ver_Byte16_06 "MBMU硬件版本号最高字节Byte16对应ASCII码";
CM_ SG_ 2416307863 M2P_Cfg4_HW_Ver_Byte9_07 "MBMU硬件版本号Byte9对应ASCII码";
CM_ SG_ 2416307863 M2P_Cfg4_HW_Ver_Byte10_07 "MBMU硬件版本号Byte10对应ASCII码";
CM_ SG_ 2416307863 M2P_Cfg4_HW_Ver_Byte11_07 "MBMU硬件版本号Byte11对应ASCII码";
CM_ SG_ 2416307863 M2P_Cfg4_HW_Ver_Byte12_07 "MBMU硬件版本号Byte12对应ASCII码";
CM_ SG_ 2416307863 M2P_Cfg4_HW_Ver_Byte13_07 "MBMU硬件版本号Byte13对应ASCII码";
CM_ SG_ 2416307863 M2P_Cfg4_HW_Ver_Byte14_07 "MBMU硬件版本号Byte14对应ASCII码";
CM_ SG_ 2416307863 M2P_Cfg4_HW_Ver_Byte15_07 "MBMU硬件版本号Byte15对应ASCII码";
CM_ SG_ 2416307863 M2P_Cfg4_HW_Ver_Byte16_07 "MBMU硬件版本号最高字节Byte16对应ASCII码";
CM_ SG_ 2416307864 M2P_Cfg4_HW_Ver_Byte9_08 "MBMU硬件版本号Byte9对应ASCII码";
CM_ SG_ 2416307864 M2P_Cfg4_HW_Ver_Byte10_08 "MBMU硬件版本号Byte10对应ASCII码";
CM_ SG_ 2416307864 M2P_Cfg4_HW_Ver_Byte11_08 "MBMU硬件版本号Byte11对应ASCII码";
CM_ SG_ 2416307864 M2P_Cfg4_HW_Ver_Byte12_08 "MBMU硬件版本号Byte12对应ASCII码";
CM_ SG_ 2416307864 M2P_Cfg4_HW_Ver_Byte13_08 "MBMU硬件版本号Byte13对应ASCII码";
CM_ SG_ 2416307864 M2P_Cfg4_HW_Ver_Byte14_08 "MBMU硬件版本号Byte14对应ASCII码";
CM_ SG_ 2416307864 M2P_Cfg4_HW_Ver_Byte15_08 "MBMU硬件版本号Byte15对应ASCII码";
CM_ SG_ 2416307864 M2P_Cfg4_HW_Ver_Byte16_08 "MBMU硬件版本号最高字节Byte16对应ASCII码";
CM_ SG_ 2416307865 M2P_Cfg4_HW_Ver_Byte9_09 "MBMU硬件版本号Byte9对应ASCII码";
CM_ SG_ 2416307865 M2P_Cfg4_HW_Ver_Byte10_09 "MBMU硬件版本号Byte10对应ASCII码";
CM_ SG_ 2416307865 M2P_Cfg4_HW_Ver_Byte11_09 "MBMU硬件版本号Byte11对应ASCII码";
CM_ SG_ 2416307865 M2P_Cfg4_HW_Ver_Byte12_09 "MBMU硬件版本号Byte12对应ASCII码";
CM_ SG_ 2416307865 M2P_Cfg4_HW_Ver_Byte13_09 "MBMU硬件版本号Byte13对应ASCII码";
CM_ SG_ 2416307865 M2P_Cfg4_HW_Ver_Byte14_09 "MBMU硬件版本号Byte14对应ASCII码";
CM_ SG_ 2416307865 M2P_Cfg4_HW_Ver_Byte15_09 "MBMU硬件版本号Byte15对应ASCII码";
CM_ SG_ 2416307865 M2P_Cfg4_HW_Ver_Byte16_09 "MBMU硬件版本号最高字节Byte16对应ASCII码";
CM_ SG_ 2416307866 M2P_Cfg4_HW_Ver_Byte9_10 "MBMU硬件版本号Byte9对应ASCII码";
CM_ SG_ 2416307866 M2P_Cfg4_HW_Ver_Byte10_10 "MBMU硬件版本号Byte10对应ASCII码";
CM_ SG_ 2416307866 M2P_Cfg4_HW_Ver_Byte11_10 "MBMU硬件版本号Byte11对应ASCII码";
CM_ SG_ 2416307866 M2P_Cfg4_HW_Ver_Byte12_10 "MBMU硬件版本号Byte12对应ASCII码";
CM_ SG_ 2416307866 M2P_Cfg4_HW_Ver_Byte13_10 "MBMU硬件版本号Byte13对应ASCII码";
CM_ SG_ 2416307866 M2P_Cfg4_HW_Ver_Byte14_10 "MBMU硬件版本号Byte14对应ASCII码";
CM_ SG_ 2416307866 M2P_Cfg4_HW_Ver_Byte15_10 "MBMU硬件版本号Byte15对应ASCII码";
CM_ SG_ 2416307866 M2P_Cfg4_HW_Ver_Byte16_10 "MBMU硬件版本号最高字节Byte16对应ASCII码";
CM_ SG_ 2416307867 M2P_Cfg4_HW_Ver_Byte9_11 "MBMU硬件版本号Byte9对应ASCII码";
CM_ SG_ 2416307867 M2P_Cfg4_HW_Ver_Byte10_11 "MBMU硬件版本号Byte10对应ASCII码";
CM_ SG_ 2416307867 M2P_Cfg4_HW_Ver_Byte11_11 "MBMU硬件版本号Byte11对应ASCII码";
CM_ SG_ 2416307867 M2P_Cfg4_HW_Ver_Byte12_11 "MBMU硬件版本号Byte12对应ASCII码";
CM_ SG_ 2416307867 M2P_Cfg4_HW_Ver_Byte13_11 "MBMU硬件版本号Byte13对应ASCII码";
CM_ SG_ 2416307867 M2P_Cfg4_HW_Ver_Byte14_11 "MBMU硬件版本号Byte14对应ASCII码";
CM_ SG_ 2416307867 M2P_Cfg4_HW_Ver_Byte15_11 "MBMU硬件版本号Byte15对应ASCII码";
CM_ SG_ 2416307867 M2P_Cfg4_HW_Ver_Byte16_11 "MBMU硬件版本号最高字节Byte16对应ASCII码";
CM_ SG_ 2416307868 M2P_Cfg4_HW_Ver_Byte9_12 "MBMU硬件版本号Byte9对应ASCII码";
CM_ SG_ 2416307868 M2P_Cfg4_HW_Ver_Byte10_12 "MBMU硬件版本号Byte10对应ASCII码";
CM_ SG_ 2416307868 M2P_Cfg4_HW_Ver_Byte11_12 "MBMU硬件版本号Byte11对应ASCII码";
CM_ SG_ 2416307868 M2P_Cfg4_HW_Ver_Byte12_12 "MBMU硬件版本号Byte12对应ASCII码";
CM_ SG_ 2416307868 M2P_Cfg4_HW_Ver_Byte13_12 "MBMU硬件版本号Byte13对应ASCII码";
CM_ SG_ 2416307868 M2P_Cfg4_HW_Ver_Byte14_12 "MBMU硬件版本号Byte14对应ASCII码";
CM_ SG_ 2416307868 M2P_Cfg4_HW_Ver_Byte15_12 "MBMU硬件版本号Byte15对应ASCII码";
CM_ SG_ 2416307868 M2P_Cfg4_HW_Ver_Byte16_12 "MBMU硬件版本号最高字节Byte16对应ASCII码";
CM_ SG_ 2416307869 M2P_Cfg4_HW_Ver_Byte9_13 "MBMU硬件版本号Byte9对应ASCII码";
CM_ SG_ 2416307869 M2P_Cfg4_HW_Ver_Byte10_13 "MBMU硬件版本号Byte10对应ASCII码";
CM_ SG_ 2416307869 M2P_Cfg4_HW_Ver_Byte11_13 "MBMU硬件版本号Byte11对应ASCII码";
CM_ SG_ 2416307869 M2P_Cfg4_HW_Ver_Byte12_13 "MBMU硬件版本号Byte12对应ASCII码";
CM_ SG_ 2416307869 M2P_Cfg4_HW_Ver_Byte13_13 "MBMU硬件版本号Byte13对应ASCII码";
CM_ SG_ 2416307869 M2P_Cfg4_HW_Ver_Byte14_13 "MBMU硬件版本号Byte14对应ASCII码";
CM_ SG_ 2416307869 M2P_Cfg4_HW_Ver_Byte15_13 "MBMU硬件版本号Byte15对应ASCII码";
CM_ SG_ 2416307869 M2P_Cfg4_HW_Ver_Byte16_13 "MBMU硬件版本号最高字节Byte16对应ASCII码";
CM_ SG_ 2416307870 M2P_Cfg4_HW_Ver_Byte9_14 "MBMU硬件版本号Byte9对应ASCII码";
CM_ SG_ 2416307870 M2P_Cfg4_HW_Ver_Byte10_14 "MBMU硬件版本号Byte10对应ASCII码";
CM_ SG_ 2416307870 M2P_Cfg4_HW_Ver_Byte11_14 "MBMU硬件版本号Byte11对应ASCII码";
CM_ SG_ 2416307870 M2P_Cfg4_HW_Ver_Byte12_14 "MBMU硬件版本号Byte12对应ASCII码";
CM_ SG_ 2416307870 M2P_Cfg4_HW_Ver_Byte13_14 "MBMU硬件版本号Byte13对应ASCII码";
CM_ SG_ 2416307870 M2P_Cfg4_HW_Ver_Byte14_14 "MBMU硬件版本号Byte14对应ASCII码";
CM_ SG_ 2416307870 M2P_Cfg4_HW_Ver_Byte15_14 "MBMU硬件版本号Byte15对应ASCII码";
CM_ SG_ 2416307870 M2P_Cfg4_HW_Ver_Byte16_14 "MBMU硬件版本号最高字节Byte16对应ASCII码";
CM_ SG_ 2416307871 M2P_Cfg4_HW_Ver_Byte9_15 "MBMU硬件版本号Byte9对应ASCII码";
CM_ SG_ 2416307871 M2P_Cfg4_HW_Ver_Byte10_15 "MBMU硬件版本号Byte10对应ASCII码";
CM_ SG_ 2416307871 M2P_Cfg4_HW_Ver_Byte11_15 "MBMU硬件版本号Byte11对应ASCII码";
CM_ SG_ 2416307871 M2P_Cfg4_HW_Ver_Byte12_15 "MBMU硬件版本号Byte12对应ASCII码";
CM_ SG_ 2416307871 M2P_Cfg4_HW_Ver_Byte13_15 "MBMU硬件版本号Byte13对应ASCII码";
CM_ SG_ 2416307871 M2P_Cfg4_HW_Ver_Byte14_15 "MBMU硬件版本号Byte14对应ASCII码";
CM_ SG_ 2416307871 M2P_Cfg4_HW_Ver_Byte15_15 "MBMU硬件版本号Byte15对应ASCII码";
CM_ SG_ 2416307871 M2P_Cfg4_HW_Ver_Byte16_15 "MBMU硬件版本号最高字节Byte16对应ASCII码";
CM_ SG_ 2416307872 M2P_Cfg4_HW_Ver_Byte9_16 "MBMU硬件版本号Byte9对应ASCII码";
CM_ SG_ 2416307872 M2P_Cfg4_HW_Ver_Byte10_16 "MBMU硬件版本号Byte10对应ASCII码";
CM_ SG_ 2416307872 M2P_Cfg4_HW_Ver_Byte11_16 "MBMU硬件版本号Byte11对应ASCII码";
CM_ SG_ 2416307872 M2P_Cfg4_HW_Ver_Byte12_16 "MBMU硬件版本号Byte12对应ASCII码";
CM_ SG_ 2416307872 M2P_Cfg4_HW_Ver_Byte13_16 "MBMU硬件版本号Byte13对应ASCII码";
CM_ SG_ 2416307872 M2P_Cfg4_HW_Ver_Byte14_16 "MBMU硬件版本号Byte14对应ASCII码";
CM_ SG_ 2416307872 M2P_Cfg4_HW_Ver_Byte15_16 "MBMU硬件版本号Byte15对应ASCII码";
CM_ SG_ 2416307872 M2P_Cfg4_HW_Ver_Byte16_16 "MBMU硬件版本号最高字节Byte16对应ASCII码";
CM_ SG_ 2416307873 M2P_Cfg4_HW_Ver_Byte9_17 "MBMU硬件版本号Byte9对应ASCII码";
CM_ SG_ 2416307873 M2P_Cfg4_HW_Ver_Byte10_17 "MBMU硬件版本号Byte10对应ASCII码";
CM_ SG_ 2416307873 M2P_Cfg4_HW_Ver_Byte11_17 "MBMU硬件版本号Byte11对应ASCII码";
CM_ SG_ 2416307873 M2P_Cfg4_HW_Ver_Byte12_17 "MBMU硬件版本号Byte12对应ASCII码";
CM_ SG_ 2416307873 M2P_Cfg4_HW_Ver_Byte13_17 "MBMU硬件版本号Byte13对应ASCII码";
CM_ SG_ 2416307873 M2P_Cfg4_HW_Ver_Byte14_17 "MBMU硬件版本号Byte14对应ASCII码";
CM_ SG_ 2416307873 M2P_Cfg4_HW_Ver_Byte15_17 "MBMU硬件版本号Byte15对应ASCII码";
CM_ SG_ 2416307873 M2P_Cfg4_HW_Ver_Byte16_17 "MBMU硬件版本号最高字节Byte16对应ASCII码";
CM_ SG_ 2416307874 M2P_Cfg4_HW_Ver_Byte9_18 "MBMU硬件版本号Byte9对应ASCII码";
CM_ SG_ 2416307874 M2P_Cfg4_HW_Ver_Byte10_18 "MBMU硬件版本号Byte10对应ASCII码";
CM_ SG_ 2416307874 M2P_Cfg4_HW_Ver_Byte11_18 "MBMU硬件版本号Byte11对应ASCII码";
CM_ SG_ 2416307874 M2P_Cfg4_HW_Ver_Byte12_18 "MBMU硬件版本号Byte12对应ASCII码";
CM_ SG_ 2416307874 M2P_Cfg4_HW_Ver_Byte13_18 "MBMU硬件版本号Byte13对应ASCII码";
CM_ SG_ 2416307874 M2P_Cfg4_HW_Ver_Byte14_18 "MBMU硬件版本号Byte14对应ASCII码";
CM_ SG_ 2416307874 M2P_Cfg4_HW_Ver_Byte15_18 "MBMU硬件版本号Byte15对应ASCII码";
CM_ SG_ 2416307874 M2P_Cfg4_HW_Ver_Byte16_18 "MBMU硬件版本号最高字节Byte16对应ASCII码";
CM_ SG_ 2416307875 M2P_Cfg4_HW_Ver_Byte9_19 "MBMU硬件版本号Byte9对应ASCII码";
CM_ SG_ 2416307875 M2P_Cfg4_HW_Ver_Byte10_19 "MBMU硬件版本号Byte10对应ASCII码";
CM_ SG_ 2416307875 M2P_Cfg4_HW_Ver_Byte11_19 "MBMU硬件版本号Byte11对应ASCII码";
CM_ SG_ 2416307875 M2P_Cfg4_HW_Ver_Byte12_19 "MBMU硬件版本号Byte12对应ASCII码";
CM_ SG_ 2416307875 M2P_Cfg4_HW_Ver_Byte13_19 "MBMU硬件版本号Byte13对应ASCII码";
CM_ SG_ 2416307875 M2P_Cfg4_HW_Ver_Byte14_19 "MBMU硬件版本号Byte14对应ASCII码";
CM_ SG_ 2416307875 M2P_Cfg4_HW_Ver_Byte15_19 "MBMU硬件版本号Byte15对应ASCII码";
CM_ SG_ 2416307875 M2P_Cfg4_HW_Ver_Byte16_19 "MBMU硬件版本号最高字节Byte16对应ASCII码";
CM_ SG_ 2416307876 M2P_Cfg4_HW_Ver_Byte9_20 "MBMU硬件版本号Byte9对应ASCII码";
CM_ SG_ 2416307876 M2P_Cfg4_HW_Ver_Byte10_20 "MBMU硬件版本号Byte10对应ASCII码";
CM_ SG_ 2416307876 M2P_Cfg4_HW_Ver_Byte11_20 "MBMU硬件版本号Byte11对应ASCII码";
CM_ SG_ 2416307876 M2P_Cfg4_HW_Ver_Byte12_20 "MBMU硬件版本号Byte12对应ASCII码";
CM_ SG_ 2416307876 M2P_Cfg4_HW_Ver_Byte13_20 "MBMU硬件版本号Byte13对应ASCII码";
CM_ SG_ 2416307876 M2P_Cfg4_HW_Ver_Byte14_20 "MBMU硬件版本号Byte14对应ASCII码";
CM_ SG_ 2416307876 M2P_Cfg4_HW_Ver_Byte15_20 "MBMU硬件版本号Byte15对应ASCII码";
CM_ SG_ 2416307876 M2P_Cfg4_HW_Ver_Byte16_20 "MBMU硬件版本号最高字节Byte16对应ASCII码";
CM_ SG_ 2416307877 M2P_Cfg4_HW_Ver_Byte9_21 "MBMU硬件版本号Byte9对应ASCII码";
CM_ SG_ 2416307877 M2P_Cfg4_HW_Ver_Byte10_21 "MBMU硬件版本号Byte10对应ASCII码";
CM_ SG_ 2416307877 M2P_Cfg4_HW_Ver_Byte11_21 "MBMU硬件版本号Byte11对应ASCII码";
CM_ SG_ 2416307877 M2P_Cfg4_HW_Ver_Byte12_21 "MBMU硬件版本号Byte12对应ASCII码";
CM_ SG_ 2416307877 M2P_Cfg4_HW_Ver_Byte13_21 "MBMU硬件版本号Byte13对应ASCII码";
CM_ SG_ 2416307877 M2P_Cfg4_HW_Ver_Byte14_21 "MBMU硬件版本号Byte14对应ASCII码";
CM_ SG_ 2416307877 M2P_Cfg4_HW_Ver_Byte15_21 "MBMU硬件版本号Byte15对应ASCII码";
CM_ SG_ 2416307877 M2P_Cfg4_HW_Ver_Byte16_21 "MBMU硬件版本号最高字节Byte16对应ASCII码";
CM_ SG_ 2416307878 M2P_Cfg4_HW_Ver_Byte9_22 "MBMU硬件版本号Byte9对应ASCII码";
CM_ SG_ 2416307878 M2P_Cfg4_HW_Ver_Byte10_22 "MBMU硬件版本号Byte10对应ASCII码";
CM_ SG_ 2416307878 M2P_Cfg4_HW_Ver_Byte11_22 "MBMU硬件版本号Byte11对应ASCII码";
CM_ SG_ 2416307878 M2P_Cfg4_HW_Ver_Byte12_22 "MBMU硬件版本号Byte12对应ASCII码";
CM_ SG_ 2416307878 M2P_Cfg4_HW_Ver_Byte13_22 "MBMU硬件版本号Byte13对应ASCII码";
CM_ SG_ 2416307878 M2P_Cfg4_HW_Ver_Byte14_22 "MBMU硬件版本号Byte14对应ASCII码";
CM_ SG_ 2416307878 M2P_Cfg4_HW_Ver_Byte15_22 "MBMU硬件版本号Byte15对应ASCII码";
CM_ SG_ 2416307878 M2P_Cfg4_HW_Ver_Byte16_22 "MBMU硬件版本号最高字节Byte16对应ASCII码";
CM_ SG_ 2416307879 M2P_Cfg4_HW_Ver_Byte9_23 "MBMU硬件版本号Byte9对应ASCII码";
CM_ SG_ 2416307879 M2P_Cfg4_HW_Ver_Byte10_23 "MBMU硬件版本号Byte10对应ASCII码";
CM_ SG_ 2416307879 M2P_Cfg4_HW_Ver_Byte11_23 "MBMU硬件版本号Byte11对应ASCII码";
CM_ SG_ 2416307879 M2P_Cfg4_HW_Ver_Byte12_23 "MBMU硬件版本号Byte12对应ASCII码";
CM_ SG_ 2416307879 M2P_Cfg4_HW_Ver_Byte13_23 "MBMU硬件版本号Byte13对应ASCII码";
CM_ SG_ 2416307879 M2P_Cfg4_HW_Ver_Byte14_23 "MBMU硬件版本号Byte14对应ASCII码";
CM_ SG_ 2416307879 M2P_Cfg4_HW_Ver_Byte15_23 "MBMU硬件版本号Byte15对应ASCII码";
CM_ SG_ 2416307879 M2P_Cfg4_HW_Ver_Byte16_23 "MBMU硬件版本号最高字节Byte16对应ASCII码";
CM_ SG_ 2416307880 M2P_Cfg4_HW_Ver_Byte9_24 "MBMU硬件版本号Byte9对应ASCII码";
CM_ SG_ 2416307880 M2P_Cfg4_HW_Ver_Byte10_24 "MBMU硬件版本号Byte10对应ASCII码";
CM_ SG_ 2416307880 M2P_Cfg4_HW_Ver_Byte11_24 "MBMU硬件版本号Byte11对应ASCII码";
CM_ SG_ 2416307880 M2P_Cfg4_HW_Ver_Byte12_24 "MBMU硬件版本号Byte12对应ASCII码";
CM_ SG_ 2416307880 M2P_Cfg4_HW_Ver_Byte13_24 "MBMU硬件版本号Byte13对应ASCII码";
CM_ SG_ 2416307880 M2P_Cfg4_HW_Ver_Byte14_24 "MBMU硬件版本号Byte14对应ASCII码";
CM_ SG_ 2416307880 M2P_Cfg4_HW_Ver_Byte15_24 "MBMU硬件版本号Byte15对应ASCII码";
CM_ SG_ 2416307880 M2P_Cfg4_HW_Ver_Byte16_24 "MBMU硬件版本号最高字节Byte16对应ASCII码";
CM_ SG_ 2416307881 M2P_Cfg4_HW_Ver_Byte9_25 "MBMU硬件版本号Byte9对应ASCII码";
CM_ SG_ 2416307881 M2P_Cfg4_HW_Ver_Byte10_25 "MBMU硬件版本号Byte10对应ASCII码";
CM_ SG_ 2416307881 M2P_Cfg4_HW_Ver_Byte11_25 "MBMU硬件版本号Byte11对应ASCII码";
CM_ SG_ 2416307881 M2P_Cfg4_HW_Ver_Byte12_25 "MBMU硬件版本号Byte12对应ASCII码";
CM_ SG_ 2416307881 M2P_Cfg4_HW_Ver_Byte13_25 "MBMU硬件版本号Byte13对应ASCII码";
CM_ SG_ 2416307881 M2P_Cfg4_HW_Ver_Byte14_25 "MBMU硬件版本号Byte14对应ASCII码";
CM_ SG_ 2416307881 M2P_Cfg4_HW_Ver_Byte15_25 "MBMU硬件版本号Byte15对应ASCII码";
CM_ SG_ 2416307881 M2P_Cfg4_HW_Ver_Byte16_25 "MBMU硬件版本号最高字节Byte16对应ASCII码";
CM_ SG_ 2416307882 M2P_Cfg4_HW_Ver_Byte9_26 "MBMU硬件版本号Byte9对应ASCII码";
CM_ SG_ 2416307882 M2P_Cfg4_HW_Ver_Byte10_26 "MBMU硬件版本号Byte10对应ASCII码";
CM_ SG_ 2416307882 M2P_Cfg4_HW_Ver_Byte11_26 "MBMU硬件版本号Byte11对应ASCII码";
CM_ SG_ 2416307882 M2P_Cfg4_HW_Ver_Byte12_26 "MBMU硬件版本号Byte12对应ASCII码";
CM_ SG_ 2416307882 M2P_Cfg4_HW_Ver_Byte13_26 "MBMU硬件版本号Byte13对应ASCII码";
CM_ SG_ 2416307882 M2P_Cfg4_HW_Ver_Byte14_26 "MBMU硬件版本号Byte14对应ASCII码";
CM_ SG_ 2416307882 M2P_Cfg4_HW_Ver_Byte15_26 "MBMU硬件版本号Byte15对应ASCII码";
CM_ SG_ 2416307882 M2P_Cfg4_HW_Ver_Byte16_26 "MBMU硬件版本号最高字节Byte16对应ASCII码";
CM_ SG_ 2416307883 M2P_Cfg4_HW_Ver_Byte9_27 "MBMU硬件版本号Byte9对应ASCII码";
CM_ SG_ 2416307883 M2P_Cfg4_HW_Ver_Byte10_27 "MBMU硬件版本号Byte10对应ASCII码";
CM_ SG_ 2416307883 M2P_Cfg4_HW_Ver_Byte11_27 "MBMU硬件版本号Byte11对应ASCII码";
CM_ SG_ 2416307883 M2P_Cfg4_HW_Ver_Byte12_27 "MBMU硬件版本号Byte12对应ASCII码";
CM_ SG_ 2416307883 M2P_Cfg4_HW_Ver_Byte13_27 "MBMU硬件版本号Byte13对应ASCII码";
CM_ SG_ 2416307883 M2P_Cfg4_HW_Ver_Byte14_27 "MBMU硬件版本号Byte14对应ASCII码";
CM_ SG_ 2416307883 M2P_Cfg4_HW_Ver_Byte15_27 "MBMU硬件版本号Byte15对应ASCII码";
CM_ SG_ 2416307883 M2P_Cfg4_HW_Ver_Byte16_27 "MBMU硬件版本号最高字节Byte16对应ASCII码";
CM_ SG_ 2416307884 M2P_Cfg4_HW_Ver_Byte9_28 "MBMU硬件版本号Byte9对应ASCII码";
CM_ SG_ 2416307884 M2P_Cfg4_HW_Ver_Byte10_28 "MBMU硬件版本号Byte10对应ASCII码";
CM_ SG_ 2416307884 M2P_Cfg4_HW_Ver_Byte11_28 "MBMU硬件版本号Byte11对应ASCII码";
CM_ SG_ 2416307884 M2P_Cfg4_HW_Ver_Byte12_28 "MBMU硬件版本号Byte12对应ASCII码";
CM_ SG_ 2416307884 M2P_Cfg4_HW_Ver_Byte13_28 "MBMU硬件版本号Byte13对应ASCII码";
CM_ SG_ 2416307884 M2P_Cfg4_HW_Ver_Byte14_28 "MBMU硬件版本号Byte14对应ASCII码";
CM_ SG_ 2416307884 M2P_Cfg4_HW_Ver_Byte15_28 "MBMU硬件版本号Byte15对应ASCII码";
CM_ SG_ 2416307884 M2P_Cfg4_HW_Ver_Byte16_28 "MBMU硬件版本号最高字节Byte16对应ASCII码";
CM_ SG_ 2416307885 M2P_Cfg4_HW_Ver_Byte9_29 "MBMU硬件版本号Byte9对应ASCII码";
CM_ SG_ 2416307885 M2P_Cfg4_HW_Ver_Byte10_29 "MBMU硬件版本号Byte10对应ASCII码";
CM_ SG_ 2416307885 M2P_Cfg4_HW_Ver_Byte11_29 "MBMU硬件版本号Byte11对应ASCII码";
CM_ SG_ 2416307885 M2P_Cfg4_HW_Ver_Byte12_29 "MBMU硬件版本号Byte12对应ASCII码";
CM_ SG_ 2416307885 M2P_Cfg4_HW_Ver_Byte13_29 "MBMU硬件版本号Byte13对应ASCII码";
CM_ SG_ 2416307885 M2P_Cfg4_HW_Ver_Byte14_29 "MBMU硬件版本号Byte14对应ASCII码";
CM_ SG_ 2416307885 M2P_Cfg4_HW_Ver_Byte15_29 "MBMU硬件版本号Byte15对应ASCII码";
CM_ SG_ 2416307885 M2P_Cfg4_HW_Ver_Byte16_29 "MBMU硬件版本号最高字节Byte16对应ASCII码";
CM_ SG_ 2416307886 M2P_Cfg4_HW_Ver_Byte9_30 "MBMU硬件版本号Byte9对应ASCII码";
CM_ SG_ 2416307886 M2P_Cfg4_HW_Ver_Byte10_30 "MBMU硬件版本号Byte10对应ASCII码";
CM_ SG_ 2416307886 M2P_Cfg4_HW_Ver_Byte11_30 "MBMU硬件版本号Byte11对应ASCII码";
CM_ SG_ 2416307886 M2P_Cfg4_HW_Ver_Byte12_30 "MBMU硬件版本号Byte12对应ASCII码";
CM_ SG_ 2416307886 M2P_Cfg4_HW_Ver_Byte13_30 "MBMU硬件版本号Byte13对应ASCII码";
CM_ SG_ 2416307886 M2P_Cfg4_HW_Ver_Byte14_30 "MBMU硬件版本号Byte14对应ASCII码";
CM_ SG_ 2416307886 M2P_Cfg4_HW_Ver_Byte15_30 "MBMU硬件版本号Byte15对应ASCII码";
CM_ SG_ 2416307886 M2P_Cfg4_HW_Ver_Byte16_30 "MBMU硬件版本号最高字节Byte16对应ASCII码";
CM_ SG_ 2416307887 M2P_Cfg4_HW_Ver_Byte9_31 "MBMU硬件版本号Byte9对应ASCII码";
CM_ SG_ 2416307887 M2P_Cfg4_HW_Ver_Byte10_31 "MBMU硬件版本号Byte10对应ASCII码";
CM_ SG_ 2416307887 M2P_Cfg4_HW_Ver_Byte11_31 "MBMU硬件版本号Byte11对应ASCII码";
CM_ SG_ 2416307887 M2P_Cfg4_HW_Ver_Byte12_31 "MBMU硬件版本号Byte12对应ASCII码";
CM_ SG_ 2416307887 M2P_Cfg4_HW_Ver_Byte13_31 "MBMU硬件版本号Byte13对应ASCII码";
CM_ SG_ 2416307887 M2P_Cfg4_HW_Ver_Byte14_31 "MBMU硬件版本号Byte14对应ASCII码";
CM_ SG_ 2416307887 M2P_Cfg4_HW_Ver_Byte15_31 "MBMU硬件版本号Byte15对应ASCII码";
CM_ SG_ 2416307887 M2P_Cfg4_HW_Ver_Byte16_31 "MBMU硬件版本号最高字节Byte16对应ASCII码";
CM_ SG_ 2416373393 M2P_Cfg5_MBMU_Add_01 "MBMU的地址";
CM_ SG_ 2416373393 S_U08_M2P_Cfg5_SBMUs_Num "MBMU当前管理的SBMU数目";
CM_ SG_ 2416373393 M2P_Cfg5_TnkRunAmnt_01 "系统正常工作所需最少的电柜数量";
CM_ SG_ 2416373393 M2P_Cfg5_ProtocolA_Ver_01 "ACAN通信协议版本号(0x10表示V1.0,0x25表示V2.5依次类推)";
CM_ SG_ 2416373394 M2P_Cfg5_MBMU_Add_02 "MBMU的地址";
CM_ SG_ 2416373394 S_U08_M2P_Cfg5_SBMUs_Num "MBMU当前管理的SBMU数目";
CM_ SG_ 2416373394 M2P_Cfg5_TnkRunAmnt_02 "系统正常工作所需最少的电柜数量";
CM_ SG_ 2416373394 M2P_Cfg5_ProtocolA_Ver_02 "ACAN通信协议版本号(0x10表示V1.0,0x25表示V2.5依次类推)";
CM_ SG_ 2416373395 M2P_Cfg5_MBMU_Add_03 "MBMU的地址";
CM_ SG_ 2416373395 S_U08_M2P_Cfg5_SBMUs_Num "MBMU当前管理的SBMU数目";
CM_ SG_ 2416373395 M2P_Cfg5_TnkRunAmnt_03 "系统正常工作所需最少的电柜数量";
CM_ SG_ 2416373395 M2P_Cfg5_ProtocolA_Ver_03 "ACAN通信协议版本号(0x10表示V1.0,0x25表示V2.5依次类推)";
CM_ SG_ 2416373396 M2P_Cfg5_MBMU_Add_04 "MBMU的地址";
CM_ SG_ 2416373396 S_U08_M2P_Cfg5_SBMUs_Num "MBMU当前管理的SBMU数目";
CM_ SG_ 2416373396 M2P_Cfg5_TnkRunAmnt_04 "系统正常工作所需最少的电柜数量";
CM_ SG_ 2416373396 M2P_Cfg5_ProtocolA_Ver_04 "ACAN通信协议版本号(0x10表示V1.0,0x25表示V2.5依次类推)";
CM_ SG_ 2416373397 M2P_Cfg5_MBMU_Add_05 "MBMU的地址";
CM_ SG_ 2416373397 S_U08_M2P_Cfg5_SBMUs_Num "MBMU当前管理的SBMU数目";
CM_ SG_ 2416373397 M2P_Cfg5_TnkRunAmnt_05 "系统正常工作所需最少的电柜数量";
CM_ SG_ 2416373397 M2P_Cfg5_ProtocolA_Ver_05 "ACAN通信协议版本号(0x10表示V1.0,0x25表示V2.5依次类推)";
CM_ SG_ 2416373398 M2P_Cfg5_MBMU_Add_06 "MBMU的地址";
CM_ SG_ 2416373398 S_U08_M2P_Cfg5_SBMUs_Num "MBMU当前管理的SBMU数目";
CM_ SG_ 2416373398 M2P_Cfg5_TnkRunAmnt_06 "系统正常工作所需最少的电柜数量";
CM_ SG_ 2416373398 M2P_Cfg5_ProtocolA_Ver_06 "ACAN通信协议版本号(0x10表示V1.0,0x25表示V2.5依次类推)";
CM_ SG_ 2416373399 M2P_Cfg5_MBMU_Add_07 "MBMU的地址";
CM_ SG_ 2416373399 S_U08_M2P_Cfg5_SBMUs_Num "MBMU当前管理的SBMU数目";
CM_ SG_ 2416373399 M2P_Cfg5_TnkRunAmnt_07 "系统正常工作所需最少的电柜数量";
CM_ SG_ 2416373399 M2P_Cfg5_ProtocolA_Ver_07 "ACAN通信协议版本号(0x10表示V1.0,0x25表示V2.5依次类推)";
CM_ SG_ 2416373400 M2P_Cfg5_MBMU_Add_08 "MBMU的地址";
CM_ SG_ 2416373400 S_U08_M2P_Cfg5_SBMUs_Num "MBMU当前管理的SBMU数目";
CM_ SG_ 2416373400 M2P_Cfg5_TnkRunAmnt_08 "系统正常工作所需最少的电柜数量";
CM_ SG_ 2416373400 M2P_Cfg5_ProtocolA_Ver_08 "ACAN通信协议版本号(0x10表示V1.0,0x25表示V2.5依次类推)";
CM_ SG_ 2416373401 M2P_Cfg5_MBMU_Add_09 "MBMU的地址";
CM_ SG_ 2416373401 S_U08_M2P_Cfg5_SBMUs_Num "MBMU当前管理的SBMU数目";
CM_ SG_ 2416373401 M2P_Cfg5_TnkRunAmnt_09 "系统正常工作所需最少的电柜数量";
CM_ SG_ 2416373401 M2P_Cfg5_ProtocolA_Ver_09 "ACAN通信协议版本号(0x10表示V1.0,0x25表示V2.5依次类推)";
CM_ SG_ 2416373402 M2P_Cfg5_MBMU_Add_10 "MBMU的地址";
CM_ SG_ 2416373402 S_U08_M2P_Cfg5_SBMUs_Num "MBMU当前管理的SBMU数目";
CM_ SG_ 2416373402 M2P_Cfg5_TnkRunAmnt_10 "系统正常工作所需最少的电柜数量";
CM_ SG_ 2416373402 M2P_Cfg5_ProtocolA_Ver_10 "ACAN通信协议版本号(0x10表示V1.0,0x25表示V2.5依次类推)";
CM_ SG_ 2416373403 M2P_Cfg5_MBMU_Add_11 "MBMU的地址";
CM_ SG_ 2416373403 S_U08_M2P_Cfg5_SBMUs_Num "MBMU当前管理的SBMU数目";
CM_ SG_ 2416373403 M2P_Cfg5_TnkRunAmnt_11 "系统正常工作所需最少的电柜数量";
CM_ SG_ 2416373403 M2P_Cfg5_ProtocolA_Ver_11 "ACAN通信协议版本号(0x10表示V1.0,0x25表示V2.5依次类推)";
CM_ SG_ 2416373404 M2P_Cfg5_MBMU_Add_12 "MBMU的地址";
CM_ SG_ 2416373404 S_U08_M2P_Cfg5_SBMUs_Num "MBMU当前管理的SBMU数目";
CM_ SG_ 2416373404 M2P_Cfg5_TnkRunAmnt_12 "系统正常工作所需最少的电柜数量";
CM_ SG_ 2416373404 M2P_Cfg5_ProtocolA_Ver_12 "ACAN通信协议版本号(0x10表示V1.0,0x25表示V2.5依次类推)";
CM_ SG_ 2416373405 M2P_Cfg5_MBMU_Add_13 "MBMU的地址";
CM_ SG_ 2416373405 S_U08_M2P_Cfg5_SBMUs_Num "MBMU当前管理的SBMU数目";
CM_ SG_ 2416373405 M2P_Cfg5_TnkRunAmnt_13 "系统正常工作所需最少的电柜数量";
CM_ SG_ 2416373405 M2P_Cfg5_ProtocolA_Ver_13 "ACAN通信协议版本号(0x10表示V1.0,0x25表示V2.5依次类推)";
CM_ SG_ 2416373406 M2P_Cfg5_MBMU_Add_14 "MBMU的地址";
CM_ SG_ 2416373406 S_U08_M2P_Cfg5_SBMUs_Num "MBMU当前管理的SBMU数目";
CM_ SG_ 2416373406 M2P_Cfg5_TnkRunAmnt_14 "系统正常工作所需最少的电柜数量";
CM_ SG_ 2416373406 M2P_Cfg5_ProtocolA_Ver_14 "ACAN通信协议版本号(0x10表示V1.0,0x25表示V2.5依次类推)";
CM_ SG_ 2416373407 M2P_Cfg5_MBMU_Add_15 "MBMU的地址";
CM_ SG_ 2416373407 S_U08_M2P_Cfg5_SBMUs_Num "MBMU当前管理的SBMU数目";
CM_ SG_ 2416373407 M2P_Cfg5_TnkRunAmnt_15 "系统正常工作所需最少的电柜数量";
CM_ SG_ 2416373407 M2P_Cfg5_ProtocolA_Ver_15 "ACAN通信协议版本号(0x10表示V1.0,0x25表示V2.5依次类推)";
CM_ SG_ 2416373408 M2P_Cfg5_MBMU_Add_16 "MBMU的地址";
CM_ SG_ 2416373408 S_U08_M2P_Cfg5_SBMUs_Num "MBMU当前管理的SBMU数目";
CM_ SG_ 2416373408 M2P_Cfg5_TnkRunAmnt_16 "系统正常工作所需最少的电柜数量";
CM_ SG_ 2416373408 M2P_Cfg5_ProtocolA_Ver_16 "ACAN通信协议版本号(0x10表示V1.0,0x25表示V2.5依次类推)";
CM_ SG_ 2416373409 M2P_Cfg5_MBMU_Add_17 "MBMU的地址";
CM_ SG_ 2416373409 S_U08_M2P_Cfg5_SBMUs_Num "MBMU当前管理的SBMU数目";
CM_ SG_ 2416373409 M2P_Cfg5_TnkRunAmnt_17 "系统正常工作所需最少的电柜数量";
CM_ SG_ 2416373409 M2P_Cfg5_ProtocolA_Ver_17 "ACAN通信协议版本号(0x10表示V1.0,0x25表示V2.5依次类推)";
CM_ SG_ 2416373410 M2P_Cfg5_MBMU_Add_18 "MBMU的地址";
CM_ SG_ 2416373410 S_U08_M2P_Cfg5_SBMUs_Num "MBMU当前管理的SBMU数目";
CM_ SG_ 2416373410 M2P_Cfg5_TnkRunAmnt_18 "系统正常工作所需最少的电柜数量";
CM_ SG_ 2416373410 M2P_Cfg5_ProtocolA_Ver_18 "ACAN通信协议版本号(0x10表示V1.0,0x25表示V2.5依次类推)";
CM_ SG_ 2416373411 M2P_Cfg5_MBMU_Add_19 "MBMU的地址";
CM_ SG_ 2416373411 S_U08_M2P_Cfg5_SBMUs_Num "MBMU当前管理的SBMU数目";
CM_ SG_ 2416373411 M2P_Cfg5_TnkRunAmnt_19 "系统正常工作所需最少的电柜数量";
CM_ SG_ 2416373411 M2P_Cfg5_ProtocolA_Ver_19 "ACAN通信协议版本号(0x10表示V1.0,0x25表示V2.5依次类推)";
CM_ SG_ 2416373412 M2P_Cfg5_MBMU_Add_20 "MBMU的地址";
CM_ SG_ 2416373412 S_U08_M2P_Cfg5_SBMUs_Num "MBMU当前管理的SBMU数目";
CM_ SG_ 2416373412 M2P_Cfg5_TnkRunAmnt_20 "系统正常工作所需最少的电柜数量";
CM_ SG_ 2416373412 M2P_Cfg5_ProtocolA_Ver_20 "ACAN通信协议版本号(0x10表示V1.0,0x25表示V2.5依次类推)";
CM_ SG_ 2416373413 M2P_Cfg5_MBMU_Add_21 "MBMU的地址";
CM_ SG_ 2416373413 S_U08_M2P_Cfg5_SBMUs_Num "MBMU当前管理的SBMU数目";
CM_ SG_ 2416373413 M2P_Cfg5_TnkRunAmnt_21 "系统正常工作所需最少的电柜数量";
CM_ SG_ 2416373413 M2P_Cfg5_ProtocolA_Ver_21 "ACAN通信协议版本号(0x10表示V1.0,0x25表示V2.5依次类推)";
CM_ SG_ 2416373414 M2P_Cfg5_MBMU_Add_22 "MBMU的地址";
CM_ SG_ 2416373414 S_U08_M2P_Cfg5_SBMUs_Num "MBMU当前管理的SBMU数目";
CM_ SG_ 2416373414 M2P_Cfg5_TnkRunAmnt_22 "系统正常工作所需最少的电柜数量";
CM_ SG_ 2416373414 M2P_Cfg5_ProtocolA_Ver_22 "ACAN通信协议版本号(0x10表示V1.0,0x25表示V2.5依次类推)";
CM_ SG_ 2416373415 M2P_Cfg5_MBMU_Add_23 "MBMU的地址";
CM_ SG_ 2416373415 S_U08_M2P_Cfg5_SBMUs_Num "MBMU当前管理的SBMU数目";
CM_ SG_ 2416373415 M2P_Cfg5_TnkRunAmnt_23 "系统正常工作所需最少的电柜数量";
CM_ SG_ 2416373415 M2P_Cfg5_ProtocolA_Ver_23 "ACAN通信协议版本号(0x10表示V1.0,0x25表示V2.5依次类推)";
CM_ SG_ 2416373416 M2P_Cfg5_MBMU_Add_24 "MBMU的地址";
CM_ SG_ 2416373416 S_U08_M2P_Cfg5_SBMUs_Num "MBMU当前管理的SBMU数目";
CM_ SG_ 2416373416 M2P_Cfg5_TnkRunAmnt_24 "系统正常工作所需最少的电柜数量";
CM_ SG_ 2416373416 M2P_Cfg5_ProtocolA_Ver_24 "ACAN通信协议版本号(0x10表示V1.0,0x25表示V2.5依次类推)";
CM_ SG_ 2416373417 M2P_Cfg5_MBMU_Add_25 "MBMU的地址";
CM_ SG_ 2416373417 S_U08_M2P_Cfg5_SBMUs_Num "MBMU当前管理的SBMU数目";
CM_ SG_ 2416373417 M2P_Cfg5_TnkRunAmnt_25 "系统正常工作所需最少的电柜数量";
CM_ SG_ 2416373417 M2P_Cfg5_ProtocolA_Ver_25 "ACAN通信协议版本号(0x10表示V1.0,0x25表示V2.5依次类推)";
CM_ SG_ 2416373418 M2P_Cfg5_MBMU_Add_26 "MBMU的地址";
CM_ SG_ 2416373418 S_U08_M2P_Cfg5_SBMUs_Num "MBMU当前管理的SBMU数目";
CM_ SG_ 2416373418 M2P_Cfg5_TnkRunAmnt_26 "系统正常工作所需最少的电柜数量";
CM_ SG_ 2416373418 M2P_Cfg5_ProtocolA_Ver_26 "ACAN通信协议版本号(0x10表示V1.0,0x25表示V2.5依次类推)";
CM_ SG_ 2416373419 M2P_Cfg5_MBMU_Add_27 "MBMU的地址";
CM_ SG_ 2416373419 S_U08_M2P_Cfg5_SBMUs_Num "MBMU当前管理的SBMU数目";
CM_ SG_ 2416373419 M2P_Cfg5_TnkRunAmnt_27 "系统正常工作所需最少的电柜数量";
CM_ SG_ 2416373419 M2P_Cfg5_ProtocolA_Ver_27 "ACAN通信协议版本号(0x10表示V1.0,0x25表示V2.5依次类推)";
CM_ SG_ 2416373420 M2P_Cfg5_MBMU_Add_28 "MBMU的地址";
CM_ SG_ 2416373420 S_U08_M2P_Cfg5_SBMUs_Num "MBMU当前管理的SBMU数目";
CM_ SG_ 2416373420 M2P_Cfg5_TnkRunAmnt_28 "系统正常工作所需最少的电柜数量";
CM_ SG_ 2416373420 M2P_Cfg5_ProtocolA_Ver_28 "ACAN通信协议版本号(0x10表示V1.0,0x25表示V2.5依次类推)";
CM_ SG_ 2416373421 M2P_Cfg5_MBMU_Add_29 "MBMU的地址";
CM_ SG_ 2416373421 S_U08_M2P_Cfg5_SBMUs_Num "MBMU当前管理的SBMU数目";
CM_ SG_ 2416373421 M2P_Cfg5_TnkRunAmnt_29 "系统正常工作所需最少的电柜数量";
CM_ SG_ 2416373421 M2P_Cfg5_ProtocolA_Ver_29 "ACAN通信协议版本号(0x10表示V1.0,0x25表示V2.5依次类推)";
CM_ SG_ 2416373422 M2P_Cfg5_MBMU_Add_30 "MBMU的地址";
CM_ SG_ 2416373422 S_U08_M2P_Cfg5_SBMUs_Num "MBMU当前管理的SBMU数目";
CM_ SG_ 2416373422 M2P_Cfg5_TnkRunAmnt_30 "系统正常工作所需最少的电柜数量";
CM_ SG_ 2416373422 M2P_Cfg5_ProtocolA_Ver_30 "ACAN通信协议版本号(0x10表示V1.0,0x25表示V2.5依次类推)";
CM_ SG_ 2416373423 M2P_Cfg5_MBMU_Add_31 "MBMU的地址";
CM_ SG_ 2416373423 S_U08_M2P_Cfg5_SBMUs_Num "MBMU当前管理的SBMU数目";
CM_ SG_ 2416373423 M2P_Cfg5_TnkRunAmnt_31 "系统正常工作所需最少的电柜数量";
CM_ SG_ 2416373423 M2P_Cfg5_ProtocolA_Ver_31 "ACAN通信协议版本号(0x10表示V1.0,0x25表示V2.5依次类推)";
CM_ SG_ 2416438929 M2P_Lmt1_Iso_1_01 "电池簇一级报警绝缘电阻";
CM_ SG_ 2416438929 M2P_Lmt1_Iso_2_01 "电池簇二级报警绝缘电阻";
CM_ SG_ 2416438929 M2P_Lmt1_Iso_3_01 "电池簇三级报警绝缘电阻";
CM_ SG_ 2416438929 M2P_Lmt1_BatClusterCurWarn_1_01 "电池簇间环流越限一级报警值(260)";
CM_ SG_ 2416438930 M2P_Lmt1_Iso_1_02 "电池簇一级报警绝缘电阻";
CM_ SG_ 2416438930 M2P_Lmt1_Iso_2_02 "电池簇二级报警绝缘电阻";
CM_ SG_ 2416438930 M2P_Lmt1_Iso_3_02 "电池簇三级报警绝缘电阻";
CM_ SG_ 2416438930 M2P_Lmt1_BatClusterCurWarn_1_02 "电池簇间环流越限一级报警值(260)";
CM_ SG_ 2416438931 M2P_Lmt1_Iso_1_03 "电池簇一级报警绝缘电阻";
CM_ SG_ 2416438931 M2P_Lmt1_Iso_2_03 "电池簇二级报警绝缘电阻";
CM_ SG_ 2416438931 M2P_Lmt1_Iso_3_03 "电池簇三级报警绝缘电阻";
CM_ SG_ 2416438931 M2P_Lmt1_BatClusterCurWarn_1_03 "电池簇间环流越限一级报警值(260)";
CM_ SG_ 2416438932 M2P_Lmt1_Iso_1_04 "电池簇一级报警绝缘电阻";
CM_ SG_ 2416438932 M2P_Lmt1_Iso_2_04 "电池簇二级报警绝缘电阻";
CM_ SG_ 2416438932 M2P_Lmt1_Iso_3_04 "电池簇三级报警绝缘电阻";
CM_ SG_ 2416438932 M2P_Lmt1_BatClusterCurWarn_1_04 "电池簇间环流越限一级报警值(260)";
CM_ SG_ 2416438933 M2P_Lmt1_Iso_1_05 "电池簇一级报警绝缘电阻";
CM_ SG_ 2416438933 M2P_Lmt1_Iso_2_05 "电池簇二级报警绝缘电阻";
CM_ SG_ 2416438933 M2P_Lmt1_Iso_3_05 "电池簇三级报警绝缘电阻";
CM_ SG_ 2416438933 M2P_Lmt1_BatClusterCurWarn_1_05 "电池簇间环流越限一级报警值(260)";
CM_ SG_ 2416438934 M2P_Lmt1_Iso_1_06 "电池簇一级报警绝缘电阻";
CM_ SG_ 2416438934 M2P_Lmt1_Iso_2_06 "电池簇二级报警绝缘电阻";
CM_ SG_ 2416438934 M2P_Lmt1_Iso_3_06 "电池簇三级报警绝缘电阻";
CM_ SG_ 2416438934 M2P_Lmt1_BatClusterCurWarn_1_06 "电池簇间环流越限一级报警值(260)";
CM_ SG_ 2416438935 M2P_Lmt1_Iso_1_07 "电池簇一级报警绝缘电阻";
CM_ SG_ 2416438935 M2P_Lmt1_Iso_2_07 "电池簇二级报警绝缘电阻";
CM_ SG_ 2416438935 M2P_Lmt1_Iso_3_07 "电池簇三级报警绝缘电阻";
CM_ SG_ 2416438935 M2P_Lmt1_BatClusterCurWarn_1_07 "电池簇间环流越限一级报警值(260)";
CM_ SG_ 2416438936 M2P_Lmt1_Iso_1_08 "电池簇一级报警绝缘电阻";
CM_ SG_ 2416438936 M2P_Lmt1_Iso_2_08 "电池簇二级报警绝缘电阻";
CM_ SG_ 2416438936 M2P_Lmt1_Iso_3_08 "电池簇三级报警绝缘电阻";
CM_ SG_ 2416438936 M2P_Lmt1_BatClusterCurWarn_1_08 "电池簇间环流越限一级报警值(260)";
CM_ SG_ 2416438937 M2P_Lmt1_Iso_1_09 "电池簇一级报警绝缘电阻";
CM_ SG_ 2416438937 M2P_Lmt1_Iso_2_09 "电池簇二级报警绝缘电阻";
CM_ SG_ 2416438937 M2P_Lmt1_Iso_3_09 "电池簇三级报警绝缘电阻";
CM_ SG_ 2416438937 M2P_Lmt1_BatClusterCurWarn_1_09 "电池簇间环流越限一级报警值(260)";
CM_ SG_ 2416438938 M2P_Lmt1_Iso_1_10 "电池簇一级报警绝缘电阻";
CM_ SG_ 2416438938 M2P_Lmt1_Iso_2_10 "电池簇二级报警绝缘电阻";
CM_ SG_ 2416438938 M2P_Lmt1_Iso_3_10 "电池簇三级报警绝缘电阻";
CM_ SG_ 2416438938 M2P_Lmt1_BatClusterCurWarn_1_10 "电池簇间环流越限一级报警值(260)";
CM_ SG_ 2416438939 M2P_Lmt1_Iso_1_11 "电池簇一级报警绝缘电阻";
CM_ SG_ 2416438939 M2P_Lmt1_Iso_2_11 "电池簇二级报警绝缘电阻";
CM_ SG_ 2416438939 M2P_Lmt1_Iso_3_11 "电池簇三级报警绝缘电阻";
CM_ SG_ 2416438939 M2P_Lmt1_BatClusterCurWarn_1_11 "电池簇间环流越限一级报警值(260)";
CM_ SG_ 2416438940 M2P_Lmt1_Iso_1_12 "电池簇一级报警绝缘电阻";
CM_ SG_ 2416438940 M2P_Lmt1_Iso_2_12 "电池簇二级报警绝缘电阻";
CM_ SG_ 2416438940 M2P_Lmt1_Iso_3_12 "电池簇三级报警绝缘电阻";
CM_ SG_ 2416438940 M2P_Lmt1_BatClusterCurWarn_1_12 "电池簇间环流越限一级报警值(260)";
CM_ SG_ 2416438941 M2P_Lmt1_Iso_1_13 "电池簇一级报警绝缘电阻";
CM_ SG_ 2416438941 M2P_Lmt1_Iso_2_13 "电池簇二级报警绝缘电阻";
CM_ SG_ 2416438941 M2P_Lmt1_Iso_3_13 "电池簇三级报警绝缘电阻";
CM_ SG_ 2416438941 M2P_Lmt1_BatClusterCurWarn_1_13 "电池簇间环流越限一级报警值(260)";
CM_ SG_ 2416438942 M2P_Lmt1_Iso_1_14 "电池簇一级报警绝缘电阻";
CM_ SG_ 2416438942 M2P_Lmt1_Iso_2_14 "电池簇二级报警绝缘电阻";
CM_ SG_ 2416438942 M2P_Lmt1_Iso_3_14 "电池簇三级报警绝缘电阻";
CM_ SG_ 2416438942 M2P_Lmt1_BatClusterCurWarn_1_14 "电池簇间环流越限一级报警值(260)";
CM_ SG_ 2416438943 M2P_Lmt1_Iso_1_15 "电池簇一级报警绝缘电阻";
CM_ SG_ 2416438943 M2P_Lmt1_Iso_2_15 "电池簇二级报警绝缘电阻";
CM_ SG_ 2416438943 M2P_Lmt1_Iso_3_15 "电池簇三级报警绝缘电阻";
CM_ SG_ 2416438943 M2P_Lmt1_BatClusterCurWarn_1_15 "电池簇间环流越限一级报警值(260)";
CM_ SG_ 2416438944 M2P_Lmt1_Iso_1_16 "电池簇一级报警绝缘电阻";
CM_ SG_ 2416438944 M2P_Lmt1_Iso_2_16 "电池簇二级报警绝缘电阻";
CM_ SG_ 2416438944 M2P_Lmt1_Iso_3_16 "电池簇三级报警绝缘电阻";
CM_ SG_ 2416438944 M2P_Lmt1_BatClusterCurWarn_1_16 "电池簇间环流越限一级报警值(260)";
CM_ SG_ 2416438945 M2P_Lmt1_Iso_1_17 "电池簇一级报警绝缘电阻";
CM_ SG_ 2416438945 M2P_Lmt1_Iso_2_17 "电池簇二级报警绝缘电阻";
CM_ SG_ 2416438945 M2P_Lmt1_Iso_3_17 "电池簇三级报警绝缘电阻";
CM_ SG_ 2416438945 M2P_Lmt1_BatClusterCurWarn_1_17 "电池簇间环流越限一级报警值(260)";
CM_ SG_ 2416438946 M2P_Lmt1_Iso_1_18 "电池簇一级报警绝缘电阻";
CM_ SG_ 2416438946 M2P_Lmt1_Iso_2_18 "电池簇二级报警绝缘电阻";
CM_ SG_ 2416438946 M2P_Lmt1_Iso_3_18 "电池簇三级报警绝缘电阻";
CM_ SG_ 2416438946 M2P_Lmt1_BatClusterCurWarn_1_18 "电池簇间环流越限一级报警值(260)";
CM_ SG_ 2416438947 M2P_Lmt1_Iso_1_19 "电池簇一级报警绝缘电阻";
CM_ SG_ 2416438947 M2P_Lmt1_Iso_2_19 "电池簇二级报警绝缘电阻";
CM_ SG_ 2416438947 M2P_Lmt1_Iso_3_19 "电池簇三级报警绝缘电阻";
CM_ SG_ 2416438947 M2P_Lmt1_BatClusterCurWarn_1_19 "电池簇间环流越限一级报警值(260)";
CM_ SG_ 2416438948 M2P_Lmt1_Iso_1_20 "电池簇一级报警绝缘电阻";
CM_ SG_ 2416438948 M2P_Lmt1_Iso_2_20 "电池簇二级报警绝缘电阻";
CM_ SG_ 2416438948 M2P_Lmt1_Iso_3_20 "电池簇三级报警绝缘电阻";
CM_ SG_ 2416438948 M2P_Lmt1_BatClusterCurWarn_1_20 "电池簇间环流越限一级报警值(260)";
CM_ SG_ 2416438949 M2P_Lmt1_Iso_1_21 "电池簇一级报警绝缘电阻";
CM_ SG_ 2416438949 M2P_Lmt1_Iso_2_21 "电池簇二级报警绝缘电阻";
CM_ SG_ 2416438949 M2P_Lmt1_Iso_3_21 "电池簇三级报警绝缘电阻";
CM_ SG_ 2416438949 M2P_Lmt1_BatClusterCurWarn_1_21 "电池簇间环流越限一级报警值(260)";
CM_ SG_ 2416438950 M2P_Lmt1_Iso_1_22 "电池簇一级报警绝缘电阻";
CM_ SG_ 2416438950 M2P_Lmt1_Iso_2_22 "电池簇二级报警绝缘电阻";
CM_ SG_ 2416438950 M2P_Lmt1_Iso_3_22 "电池簇三级报警绝缘电阻";
CM_ SG_ 2416438950 M2P_Lmt1_BatClusterCurWarn_1_22 "电池簇间环流越限一级报警值(260)";
CM_ SG_ 2416438951 M2P_Lmt1_Iso_1_23 "电池簇一级报警绝缘电阻";
CM_ SG_ 2416438951 M2P_Lmt1_Iso_2_23 "电池簇二级报警绝缘电阻";
CM_ SG_ 2416438951 M2P_Lmt1_Iso_3_23 "电池簇三级报警绝缘电阻";
CM_ SG_ 2416438951 M2P_Lmt1_BatClusterCurWarn_1_23 "电池簇间环流越限一级报警值(260)";
CM_ SG_ 2416438952 M2P_Lmt1_Iso_1_24 "电池簇一级报警绝缘电阻";
CM_ SG_ 2416438952 M2P_Lmt1_Iso_2_24 "电池簇二级报警绝缘电阻";
CM_ SG_ 2416438952 M2P_Lmt1_Iso_3_24 "电池簇三级报警绝缘电阻";
CM_ SG_ 2416438952 M2P_Lmt1_BatClusterCurWarn_1_24 "电池簇间环流越限一级报警值(260)";
CM_ SG_ 2416438953 M2P_Lmt1_Iso_1_25 "电池簇一级报警绝缘电阻";
CM_ SG_ 2416438953 M2P_Lmt1_Iso_2_25 "电池簇二级报警绝缘电阻";
CM_ SG_ 2416438953 M2P_Lmt1_Iso_3_25 "电池簇三级报警绝缘电阻";
CM_ SG_ 2416438953 M2P_Lmt1_BatClusterCurWarn_1_25 "电池簇间环流越限一级报警值(260)";
CM_ SG_ 2416438954 M2P_Lmt1_Iso_1_26 "电池簇一级报警绝缘电阻";
CM_ SG_ 2416438954 M2P_Lmt1_Iso_2_26 "电池簇二级报警绝缘电阻";
CM_ SG_ 2416438954 M2P_Lmt1_Iso_3_26 "电池簇三级报警绝缘电阻";
CM_ SG_ 2416438954 M2P_Lmt1_BatClusterCurWarn_1_26 "电池簇间环流越限一级报警值(260)";
CM_ SG_ 2416438955 M2P_Lmt1_Iso_1_27 "电池簇一级报警绝缘电阻";
CM_ SG_ 2416438955 M2P_Lmt1_Iso_2_27 "电池簇二级报警绝缘电阻";
CM_ SG_ 2416438955 M2P_Lmt1_Iso_3_27 "电池簇三级报警绝缘电阻";
CM_ SG_ 2416438955 M2P_Lmt1_BatClusterCurWarn_1_27 "电池簇间环流越限一级报警值(260)";
CM_ SG_ 2416438956 M2P_Lmt1_Iso_1_28 "电池簇一级报警绝缘电阻";
CM_ SG_ 2416438956 M2P_Lmt1_Iso_2_28 "电池簇二级报警绝缘电阻";
CM_ SG_ 2416438956 M2P_Lmt1_Iso_3_28 "电池簇三级报警绝缘电阻";
CM_ SG_ 2416438956 M2P_Lmt1_BatClusterCurWarn_1_28 "电池簇间环流越限一级报警值(260)";
CM_ SG_ 2416438957 M2P_Lmt1_Iso_1_29 "电池簇一级报警绝缘电阻";
CM_ SG_ 2416438957 M2P_Lmt1_Iso_2_29 "电池簇二级报警绝缘电阻";
CM_ SG_ 2416438957 M2P_Lmt1_Iso_3_29 "电池簇三级报警绝缘电阻";
CM_ SG_ 2416438957 M2P_Lmt1_BatClusterCurWarn_1_29 "电池簇间环流越限一级报警值(260)";
CM_ SG_ 2416438958 M2P_Lmt1_Iso_1_30 "电池簇一级报警绝缘电阻";
CM_ SG_ 2416438958 M2P_Lmt1_Iso_2_30 "电池簇二级报警绝缘电阻";
CM_ SG_ 2416438958 M2P_Lmt1_Iso_3_30 "电池簇三级报警绝缘电阻";
CM_ SG_ 2416438958 M2P_Lmt1_BatClusterCurWarn_1_30 "电池簇间环流越限一级报警值(260)";
CM_ SG_ 2416438959 M2P_Lmt1_Iso_1_31 "电池簇一级报警绝缘电阻";
CM_ SG_ 2416438959 M2P_Lmt1_Iso_2_31 "电池簇二级报警绝缘电阻";
CM_ SG_ 2416438959 M2P_Lmt1_Iso_3_31 "电池簇三级报警绝缘电阻";
CM_ SG_ 2416438959 M2P_Lmt1_BatClusterCurWarn_1_31 "电池簇间环流越限一级报警值(260)";
CM_ SG_ 2416504465 M2P_Lmt2_BatClusterCurWarn_2_01 "电池簇间环流越限二级报警值(261)";
CM_ SG_ 2416504465 M2P_Lmt2_BatClusterCurWarn_3_01 "电池簇间环流越限二级报警值(262)";
CM_ SG_ 2416504466 M2P_Lmt2_BatClusterCurWarn_2_02 "电池簇间环流越限二级报警值(261)";
CM_ SG_ 2416504466 M2P_Lmt2_BatClusterCurWarn_3_02 "电池簇间环流越限二级报警值(262)";
CM_ SG_ 2416504467 M2P_Lmt2_BatClusterCurWarn_2_03 "电池簇间环流越限二级报警值(261)";
CM_ SG_ 2416504467 M2P_Lmt2_BatClusterCurWarn_3_03 "电池簇间环流越限二级报警值(262)";
CM_ SG_ 2416504468 M2P_Lmt2_BatClusterCurWarn_2_04 "电池簇间环流越限二级报警值(261)";
CM_ SG_ 2416504468 M2P_Lmt2_BatClusterCurWarn_3_04 "电池簇间环流越限二级报警值(262)";
CM_ SG_ 2416504469 M2P_Lmt2_BatClusterCurWarn_2_05 "电池簇间环流越限二级报警值(261)";
CM_ SG_ 2416504469 M2P_Lmt2_BatClusterCurWarn_3_05 "电池簇间环流越限二级报警值(262)";
CM_ SG_ 2416504470 M2P_Lmt2_BatClusterCurWarn_2_06 "电池簇间环流越限二级报警值(261)";
CM_ SG_ 2416504470 M2P_Lmt2_BatClusterCurWarn_3_06 "电池簇间环流越限二级报警值(262)";
CM_ SG_ 2416504471 M2P_Lmt2_BatClusterCurWarn_2_07 "电池簇间环流越限二级报警值(261)";
CM_ SG_ 2416504471 M2P_Lmt2_BatClusterCurWarn_3_07 "电池簇间环流越限二级报警值(262)";
CM_ SG_ 2416504472 M2P_Lmt2_BatClusterCurWarn_2_08 "电池簇间环流越限二级报警值(261)";
CM_ SG_ 2416504472 M2P_Lmt2_BatClusterCurWarn_3_08 "电池簇间环流越限二级报警值(262)";
CM_ SG_ 2416504473 M2P_Lmt2_BatClusterCurWarn_2_09 "电池簇间环流越限二级报警值(261)";
CM_ SG_ 2416504473 M2P_Lmt2_BatClusterCurWarn_3_09 "电池簇间环流越限二级报警值(262)";
CM_ SG_ 2416504474 M2P_Lmt2_BatClusterCurWarn_2_10 "电池簇间环流越限二级报警值(261)";
CM_ SG_ 2416504474 M2P_Lmt2_BatClusterCurWarn_3_10 "电池簇间环流越限二级报警值(262)";
CM_ SG_ 2416504475 M2P_Lmt2_BatClusterCurWarn_2_11 "电池簇间环流越限二级报警值(261)";
CM_ SG_ 2416504475 M2P_Lmt2_BatClusterCurWarn_3_11 "电池簇间环流越限二级报警值(262)";
CM_ SG_ 2416504476 M2P_Lmt2_BatClusterCurWarn_2_12 "电池簇间环流越限二级报警值(261)";
CM_ SG_ 2416504476 M2P_Lmt2_BatClusterCurWarn_3_12 "电池簇间环流越限二级报警值(262)";
CM_ SG_ 2416504477 M2P_Lmt2_BatClusterCurWarn_2_13 "电池簇间环流越限二级报警值(261)";
CM_ SG_ 2416504477 M2P_Lmt2_BatClusterCurWarn_3_13 "电池簇间环流越限二级报警值(262)";
CM_ SG_ 2416504478 M2P_Lmt2_BatClusterCurWarn_2_14 "电池簇间环流越限二级报警值(261)";
CM_ SG_ 2416504478 M2P_Lmt2_BatClusterCurWarn_3_14 "电池簇间环流越限二级报警值(262)";
CM_ SG_ 2416504479 M2P_Lmt2_BatClusterCurWarn_2_15 "电池簇间环流越限二级报警值(261)";
CM_ SG_ 2416504479 M2P_Lmt2_BatClusterCurWarn_3_15 "电池簇间环流越限二级报警值(262)";
CM_ SG_ 2416504480 M2P_Lmt2_BatClusterCurWarn_2_16 "电池簇间环流越限二级报警值(261)";
CM_ SG_ 2416504480 M2P_Lmt2_BatClusterCurWarn_3_16 "电池簇间环流越限二级报警值(262)";
CM_ SG_ 2416504481 M2P_Lmt2_BatClusterCurWarn_2_17 "电池簇间环流越限二级报警值(261)";
CM_ SG_ 2416504481 M2P_Lmt2_BatClusterCurWarn_3_17 "电池簇间环流越限二级报警值(262)";
CM_ SG_ 2416504482 M2P_Lmt2_BatClusterCurWarn_2_18 "电池簇间环流越限二级报警值(261)";
CM_ SG_ 2416504482 M2P_Lmt2_BatClusterCurWarn_3_18 "电池簇间环流越限二级报警值(262)";
CM_ SG_ 2416504483 M2P_Lmt2_BatClusterCurWarn_2_19 "电池簇间环流越限二级报警值(261)";
CM_ SG_ 2416504483 M2P_Lmt2_BatClusterCurWarn_3_19 "电池簇间环流越限二级报警值(262)";
CM_ SG_ 2416504484 M2P_Lmt2_BatClusterCurWarn_2_20 "电池簇间环流越限二级报警值(261)";
CM_ SG_ 2416504484 M2P_Lmt2_BatClusterCurWarn_3_20 "电池簇间环流越限二级报警值(262)";
CM_ SG_ 2416504485 M2P_Lmt2_BatClusterCurWarn_2_21 "电池簇间环流越限二级报警值(261)";
CM_ SG_ 2416504485 M2P_Lmt2_BatClusterCurWarn_3_21 "电池簇间环流越限二级报警值(262)";
CM_ SG_ 2416504486 M2P_Lmt2_BatClusterCurWarn_2_22 "电池簇间环流越限二级报警值(261)";
CM_ SG_ 2416504486 M2P_Lmt2_BatClusterCurWarn_3_22 "电池簇间环流越限二级报警值(262)";
CM_ SG_ 2416504487 M2P_Lmt2_BatClusterCurWarn_2_23 "电池簇间环流越限二级报警值(261)";
CM_ SG_ 2416504487 M2P_Lmt2_BatClusterCurWarn_3_23 "电池簇间环流越限二级报警值(262)";
CM_ SG_ 2416504488 M2P_Lmt2_BatClusterCurWarn_2_24 "电池簇间环流越限二级报警值(261)";
CM_ SG_ 2416504488 M2P_Lmt2_BatClusterCurWarn_3_24 "电池簇间环流越限二级报警值(262)";
CM_ SG_ 2416504489 M2P_Lmt2_BatClusterCurWarn_2_25 "电池簇间环流越限二级报警值(261)";
CM_ SG_ 2416504489 M2P_Lmt2_BatClusterCurWarn_3_25 "电池簇间环流越限二级报警值(262)";
CM_ SG_ 2416504490 M2P_Lmt2_BatClusterCurWarn_2_26 "电池簇间环流越限二级报警值(261)";
CM_ SG_ 2416504490 M2P_Lmt2_BatClusterCurWarn_3_26 "电池簇间环流越限二级报警值(262)";
CM_ SG_ 2416504491 M2P_Lmt2_BatClusterCurWarn_2_27 "电池簇间环流越限二级报警值(261)";
CM_ SG_ 2416504491 M2P_Lmt2_BatClusterCurWarn_3_27 "电池簇间环流越限二级报警值(262)";
CM_ SG_ 2416504492 M2P_Lmt2_BatClusterCurWarn_2_28 "电池簇间环流越限二级报警值(261)";
CM_ SG_ 2416504492 M2P_Lmt2_BatClusterCurWarn_3_28 "电池簇间环流越限二级报警值(262)";
CM_ SG_ 2416504493 M2P_Lmt2_BatClusterCurWarn_2_29 "电池簇间环流越限二级报警值(261)";
CM_ SG_ 2416504493 M2P_Lmt2_BatClusterCurWarn_3_29 "电池簇间环流越限二级报警值(262)";
CM_ SG_ 2416504494 M2P_Lmt2_BatClusterCurWarn_2_30 "电池簇间环流越限二级报警值(261)";
CM_ SG_ 2416504494 M2P_Lmt2_BatClusterCurWarn_3_30 "电池簇间环流越限二级报警值(262)";
CM_ SG_ 2416504495 M2P_Lmt2_BatClusterCurWarn_2_31 "电池簇间环流越限二级报警值(261)";
CM_ SG_ 2416504495 M2P_Lmt2_BatClusterCurWarn_3_31 "电池簇间环流越限二级报警值(262)";
CM_ SG_ 2164391918 CRC_P2A "生命帧的CRC（未使用）";
CM_ SG_ 2164391918 ALIV_P2A "生命信号,0~15循环";
CM_ SG_ 2165506030 CRC_P2A_RTC "PC到MBMU及SBMU的对时信息的CRC";
CM_ SG_ 2165506030 RTC_Year "实时时钟年";
CM_ SG_ 2165506030 RTC_Month "实时时钟月";
CM_ SG_ 2165506030 RTC_date "实时时钟日";
CM_ SG_ 2165506030 RTC_Hour "实时时钟时";
CM_ SG_ 2165506030 RTC_minute "实时时钟分";
CM_ SG_ 2165506030 RTC_second "实时时钟秒";
CM_ SG_ 2165506030 RTC_CMD "实时时钟控制指令";
CM_ SG_ 2165407726 CRC_P2S_CMD "P2S命令帧的CRC";
CM_ SG_ 2165407726 P2S_SBMU_No "SBMU号";
CM_ SG_ 2165407726 RQ_Read_Detail_Data "对详细数据的读取(实时读取,Cyclic;同步读取,Event)";
CM_ SG_ 2165407726 P2S_CMD_Data0 "预留数据";
CM_ SG_ 2165407726 P2S_CMD_Data1 "预留数据";
CM_ SG_ 2165407726 P2S_CMD_Data2 "预留数据";
CM_ SG_ 2165407726 P2S_CMD_Data3 "预留数据";
CM_ SG_ 2165407726 P2S_CMD_Data4 "预留数据";
CM_ SG_ 2165407726 P2S_CMD_Data5 "预留数据";
CM_ SG_ 2165473262 CRC_P2S_CMD1 "PC发送给SBMU的命令数据1的CRC";
CM_ SG_ 2165473262 P2S_TrigCal_TankVolKB "PC触发SBMU进行电柜电压采样值的KB值校准";
CM_ SG_ 2165473262 P2S_Read_Cfg_Lmt "PC给SBMU的读取SBMU的配置和阈值数据命令";
CM_ SG_ 2165473262 P2S_CMD1_FanOnOff "请求指定SBMU编号的风扇(未使用)";
CM_ SG_ 2165473262 P2S_Read_CSCcfg_data "请求读取CSC的软件和硬件版本号";
CM_ SG_ 2165473262 P2S_CMD1_CB_CoolMode "冷调均衡模式指令";
CM_ SG_ 2165473262 P2S_CMD1_Data2 "预留数据";
CM_ SG_ 2165473262 P2S_CMD1_Data3 "预留数据";
CM_ SG_ 2165473262 P2S_CMD1_Data4 "预留数据";
CM_ SG_ 2165473262 P2S_CMD1_Data5 "预留数据";
CM_ SG_ 2165473262 P2S_CMD1_SBMU_No "高压采样需要kb值校准的SBMU编号";
CM_ SG_ 2433908718 P2S_Index_CRC "PC发送给SBMU的编码命令的CRC";
CM_ SG_ 2433908718 P2S_Index_Enable "PC发送给SBMU的CSC编码命令";
CM_ SG_ 2433908718 P2S_Index_Data0 "预留数据";
CM_ SG_ 2433908718 P2S_Index_Data1 "预留数据";
CM_ SG_ 2433908718 P2S_Index_Data2 "预留数据";
CM_ SG_ 2433908718 P2S_Index_Data3 "预留数据";
CM_ SG_ 2433908718 P2S_Index_Data4 "预留数据";
CM_ SG_ 2433908718 P2S_Index_Data5 "预留数据";
CM_ SG_ 2432794606 P2S_DIAG_BYTE1 "PC给SBMU的诊断报文字节1";
CM_ SG_ 2432794606 P2S_DIAG_BYTE2 "PC给SBMU的诊断报文字节2";
CM_ SG_ 2432794606 P2S_DIAG_BYTE3 "PC给SBMU的诊断报文字节3";
CM_ SG_ 2432794606 P2S_DIAG_BYTE4 "PC给SBMU的诊断报文字节4";
CM_ SG_ 2432794606 P2S_DIAG_BYTE5 "PC给SBMU的诊断报文字节5";
CM_ SG_ 2432794606 P2S_DIAG_BYTE6 "PC给SBMU的诊断报文字节6";
CM_ SG_ 2432794606 P2S_DIAG_BYTE7 "PC给SBMU的诊断报文字节7";
CM_ SG_ 2432794606 P2S_DIAG_BYTE8 "PC给SBMU的诊断报文字节8";
CM_ SG_ 2433122286 P2MSD_Cfg "PC写入SBMU/DCDC的方式选择";
CM_ SG_ 2433122286 P2MSD_Cfg_Addr "当PC写入方式为2/3时，写入SBMU/DCDC的地址 ";
CM_ SG_ 2433122286 P2MSD_Cfg_Data1 "预留数据";
CM_ SG_ 2433122286 P2MSD_Cfg_Data2 "预留数据";
CM_ SG_ 2433122286 P2MSD_Cfg_Data3 "预留数据";
CM_ SG_ 2433122286 P2MSD_Cfg_Data4 "预留数据";
CM_ SG_ 2433122286 P2MSD_Cfg_Data5 "预留数据";
CM_ SG_ 2433122286 P2MSD_Cfg_Data6 "预留数据";
CM_ SG_ 2163802095 P2S_Boot1_Data0 "依据CAN下载协议";
CM_ SG_ 2163802095 P2S_Boot1_Data1 "依据CAN下载协议";
CM_ SG_ 2163802095 P2S_Boot1_Data2 "依据CAN下载协议";
CM_ SG_ 2163802095 P2S_Boot1_Data3 "依据CAN下载协议";
CM_ SG_ 2163802095 P2S_Boot1_Data4 "依据CAN下载协议";
CM_ SG_ 2163802095 P2S_Boot1_Data5 "依据CAN下载协议";
CM_ SG_ 2163802095 P2S_Boot1_Data6 "依据CAN下载协议";
CM_ SG_ 2163802095 P2S_Boot1_Data7 "依据CAN下载协议";
CM_ SG_ 2197356527 P2S_Boot2_Data0 "依据CAN下载协议";
CM_ SG_ 2197356527 P2S_Boot2_Data1 "依据CAN下载协议";
CM_ SG_ 2197356527 P2S_Boot2_Data2 "依据CAN下载协议";
CM_ SG_ 2197356527 P2S_Boot2_Data3 "依据CAN下载协议";
CM_ SG_ 2197356527 P2S_Boot2_Data4 "依据CAN下载协议";
CM_ SG_ 2197356527 P2S_Boot2_Data5 "依据CAN下载协议";
CM_ SG_ 2197356527 P2S_Boot2_Data6 "依据CAN下载协议";
CM_ SG_ 2197356527 P2S_Boot2_Data7 "依据CAN下载协议";
CM_ SG_ 2163933167 P2S_PrgInfo_Data0 "发送的待下载总页数信息报文字节1";
CM_ SG_ 2163933167 P2S_PrgInfo_Data1 "发送的待下载总页数信息报文字节2";
CM_ SG_ 2163933167 P2S_PrgInfo_Data2 "发送的待下载总页数信息报文字节3";
CM_ SG_ 2163933167 P2S_PrgInfo_Data3 "发送的待下载总页数信息报文字节4";
CM_ SG_ 2163933167 P2S_PrgInfo_Data4 "发送的待下载总页数信息报文字节5";
CM_ SG_ 2163933167 P2S_PrgInfo_Data5 "发送的待下载总页数信息报文字节6";
CM_ SG_ 2163933167 P2S_PrgInfo_Data6 "发送的待下载总页数信息报文字节7";
CM_ SG_ 2163933167 P2S_PrgInfo_Data7 "发送的待下载总页数信息报文字节8";
CM_ SG_ 2163998703 P2S_DLoadInfo_Data0 "发送的flash程序页下载握手指令报文字节1";
CM_ SG_ 2163998703 P2S_DLoadInfo_Data1 "发送的flash程序页下载握手指令报文字节2";
CM_ SG_ 2163998703 P2S_DLoadInfo_Data2 "发送的flash程序页下载握手指令报文字节3";
CM_ SG_ 2163998703 P2S_DLoadInfo_Data3 "发送的flash程序页下载握手指令报文字节4";
CM_ SG_ 2163998703 P2S_DLoadInfo_Data4 "发送的flash程序页下载握手指令报文字节5";
CM_ SG_ 2163998703 P2S_DLoadInfo_Data5 "发送的flash程序页下载握手指令报文字节6";
CM_ SG_ 2163998703 P2S_DLoadInfo_Data6 "发送的flash程序页下载握手指令报文字节7";
CM_ SG_ 2163998703 P2S_DLoadInfo_Data7 "发送的flash程序页下载握手指令报文字节8";
CM_ SG_ 2164064239 P2S_PrgData_Data0 "发送的flash数据报文字节1";
CM_ SG_ 2164064239 P2S_PrgData_Data1 "发送的flash数据报文字节2";
CM_ SG_ 2164064239 P2S_PrgData_Data2 "发送的flash数据报文字节3";
CM_ SG_ 2164064239 P2S_PrgData_Data3 "发送的flash数据报文字节4";
CM_ SG_ 2164064239 P2S_PrgData_Data4 "发送的flash数据报文字节5";
CM_ SG_ 2164064239 P2S_PrgData_Data5 "发送的flash数据报文字节6";
CM_ SG_ 2164064239 P2S_PrgData_Data6 "发送的flash数据报文字节7";
CM_ SG_ 2164064239 P2S_PrgData_Data7 "发送的flash数据报文字节8";
CM_ SG_ 2449342447 P2S_CSCVer_Data0 "CSC软件版本号确认报文字节1";
CM_ SG_ 2449342447 P2S_CSCVer_Data1 "CSC软件版本号确认报文字节2";
CM_ SG_ 2449342447 P2S_CSCVer_Data2 "CSC软件版本号确认报文字节3";
CM_ SG_ 2449342447 P2S_CSCVer_Data3 "CSC软件版本号确认报文字节4";
CM_ SG_ 2449342447 P2S_CSCVer_Data4 "CSC软件版本号确认报文字节5";
CM_ SG_ 2449342447 P2S_CSCVer_Data5 "CSC软件版本号确认报文字节6";
CM_ SG_ 2449342447 P2S_CSCVer_Data6 "CSC软件版本号确认报文字节7";
CM_ SG_ 2449342447 P2S_CSCVer_Data7 "CSC软件版本号确认报文字节8";
CM_ SG_ 2164129775 P2S_CSCVer_Data0 "ETH下发更新CSC/IMM/SBMU报文，更新CSC需要SBMU转发";
CM_ SG_ 2164129775 P2S_CSCVer_Data1 "ETH下发更新CSC/IMM/SBMU报文，更新CSC需要SBMU转发";
CM_ SG_ 2164129775 P2S_CSCVer_Data2 "ETH下发更新CSC/IMM/SBMU报文，更新CSC需要SBMU转发";
CM_ SG_ 2164129775 P2S_CSCVer_Data3 "ETH下发更新CSC/IMM/SBMU报文，更新CSC需要SBMU转发";
CM_ SG_ 2164129775 P2S_CSCVer_Data4 "ETH下发更新CSC/IMM/SBMU报文，更新CSC需要SBMU转发";
CM_ SG_ 2164129775 P2S_CSCVer_Data5 "ETH下发更新CSC/IMM/SBMU报文，更新CSC需要SBMU转发";
CM_ SG_ 2164129775 P2S_CSCVer_Data6 "ETH下发更新CSC/IMM/SBMU报文，更新CSC需要SBMU转发";
CM_ SG_ 2164129775 P2S_CSCVer_Data7 "ETH下发更新CSC/IMM/SBMU报文，更新CSC需要SBMU转发";
CM_ SG_ 2432805614 P2M_DIAG_BYTE1 "PC给MBMU的诊断报文字节1（详见调试协议）";
CM_ SG_ 2432805614 P2M_DIAG_BYTE2 "PC给MBMU的诊断报文字节2（详见调试协议）";
CM_ SG_ 2432805614 P2M_DIAG_BYTE3 "PC给MBMU的诊断报文字节3（详见调试协议）";
CM_ SG_ 2432805614 P2M_DIAG_BYTE4 "PC给MBMU的诊断报文字节4（详见调试协议）";
CM_ SG_ 2432805614 P2M_DIAG_BYTE5 "PC给MBMU的诊断报文字节5（详见调试协议）";
CM_ SG_ 2432805614 P2M_DIAG_BYTE6 "PC给MBMU的诊断报文字节6（详见调试协议）";
CM_ SG_ 2432805614 P2M_DIAG_BYTE7 "PC给MBMU的诊断报文字节7（详见调试协议）";
CM_ SG_ 2432805614 P2M_DIAG_BYTE8 "PC给MBMU的诊断报文字节8（详见调试协议）";
CM_ SG_ 2433133294 P2M_Cfg5_MBMU_CMD "PC的编码命令 新增功能使用： 0xA0  写入  ，0x50读取；
如果需要写入多报文，使用0xA1，0xA2…               编码指令             ";
CM_ SG_ 2433133294 P2M_Cfg5_MBMU_Add "PC写入MBMU的MBMU的地址  新增功能使用： 功能编码，根据功能定义具含义                ";
CM_ SG_ 2433133294 P2E_Cfg5_MBMU_data1 "根据功能码定义和解析数据1";
CM_ SG_ 2433133294 P2E_Cfg5_MBMU_data2 "根据功能码定义和解析数据2";
CM_ SG_ 2433133294 P2E_Cfg5_MBMU_data3 "根据功能码定义和解析数据3";
CM_ SG_ 2433133294 P2E_Cfg5_MBMU_data4 "根据功能码定义和解析数据4";
CM_ SG_ 2433133294 P2E_Cfg5_MBMU_data5 "根据功能码定义和解析数据5";
CM_ SG_ 2433133294 P2E_Cfg5_MBMU_data6 "根据功能码定义和解析数据6";
CM_ SG_ 2148641518 CRC_P2M_CMD "PC给MBMU命令数据的CRC(未使用)";
CM_ SG_ 2148641518 ALIV_P2M_CMD "PC给MBMU命令数据的生命信号，0~15循环(未使用)";
CM_ SG_ 2148641518 P2M_HV_OnOff "PC给MBMU的强制高压继电器的闭合断开命令(未使用)";
CM_ SG_ 2148641518 P2M_Force_Heating "PC给MBMU的强制加热命令(未使用)";
CM_ SG_ 2148641518 P2M_ForceFan_OnorOff "PC给MBMU的强制开启或关闭风机命令，0无效命令，1强制开启，2强制关闭(未使用)";
CM_ SG_ 2148641518 P2M_ForceISO_OnorOff "PC给MBMU的强制开启或关闭绝缘诊断命令，0强制开启，1强制关闭(未使用)";
CM_ SG_ 2148641518 PCSIsoCtrlCmd "PCS控制绝缘检测接口";
CM_ SG_ 2148707054 P2M_Read_Cfg_Lmt "PC给MBMU的读取MBMU的配置和阈值数据命令";
CM_ SG_ 2148707054 Relay_Cmd "上位机闭合指令控制BMS继电器命令（转modbud 0x0381）(当前预留) 备注：后续需实现
";
CM_ SG_ 2148707054 Fault_Clean_Cmd "上位机发送的故障清除指令（转modbud 0x038C）(当前预留)
";
CM_ SG_ 2148707054 PCS_alive_counter "上位机发送的PCS 生命帧信号（转modbud 0x0380）";
CM_ SG_ 2332164073 CRC_M2I_S1 "CRC校验";
CM_ SG_ 2332164073 M2I_S1_HVS "绝缘测量电压";
CM_ SG_ 2332164073 M2I_S1_Enable "绝缘采样使能位";
CM_ SG_ 2332164073 M2I_S1_Read_Ver_Enable "读取软件版本使能位";
CM_ SG_ 2332164073 M2I_S1_Iso_PostTime "绝缘采样时间";
CM_ SG_ 2332164073 M2I_S1_SysABStableTime "电压稳定时间";
CM_ SG_ 2332164074 I2A_Info1_SW_Ver_Byte1 "IMM软件版本字节1";
CM_ SG_ 2332164074 I2A_Info1_SW_Ver_Byte2 "IMM软件版本字节2";
CM_ SG_ 2332164074 I2A_Info1_SW_Ver_Byte3 "IMM软件版本字节3";
CM_ SG_ 2332164074 I2A_Info1_SW_Ver_Byte4 "IMM软件版本字节4";
CM_ SG_ 2332164074 I2A_Info1_SW_Ver_Byte5 "IMM软件版本字节5";
CM_ SG_ 2332164074 I2A_Info1_SW_Ver_Byte6 "IMM软件版本字节6";
CM_ SG_ 2332164074 I2A_Info1_SW_Ver_Byte7 "IMM软件版本字节7";
CM_ SG_ 2332164074 I2A_Info1_SW_Ver_Byte8 "IMM软件版本字节8";
CM_ SG_ 2332164075 I2A_Info2_SW_Ver_Byte9 "IMM软件版本字节9";
CM_ SG_ 2332164075 I2A_Info2_SW_Ver_Byte10 "IMM软件版本字节10";
CM_ SG_ 2332164075 I2A_Info2_SW_Ver_Byte11 "IMM软件版本字节11";
CM_ SG_ 2332164075 I2A_Info2_SW_Ver_Byte12 "IMM软件版本字节12";
CM_ SG_ 2332164075 I2A_Info2_SW_Ver_Byte13 "IMM软件版本字节13";
CM_ SG_ 2332164075 I2A_Info2_SW_Ver_Byte14 "IMM软件版本字节14";
CM_ SG_ 2332164075 I2A_Info2_SW_Ver_Byte15 "IMM软件版本字节15";
CM_ SG_ 2332164075 I2A_Info2_SW_Ver_Byte16 "IMM软件版本字节16";
CM_ SG_ 2332164076 I2A_Info3_HW_Ver_Byte1 "IMM硬件版本字节1";
CM_ SG_ 2332164076 I2A_Info3_HW_Ver_Byte2 "IMM硬件版本字节2";
CM_ SG_ 2332164076 I2A_Info3_HW_Ver_Byte3 "IMM硬件版本字节3";
CM_ SG_ 2332164076 I2A_Info3_HW_Ver_Byte4 "IMM硬件版本字节4";
CM_ SG_ 2332164076 I2A_Info3_HW_Ver_Byte5 "IMM硬件版本字节5";
CM_ SG_ 2332164076 I2A_Info3_HW_Ver_Byte6 "IMM硬件版本字节6";
CM_ SG_ 2332164076 I2A_Info3_HW_Ver_Byte7 "IMM硬件版本字节7";
CM_ SG_ 2332164076 I2A_Info3_HW_Ver_Byte8 "IMM硬件版本字节8";
CM_ SG_ 2332164077 I2A_Info4_HW_Ver_Byte9 "IMM硬件版本字节9";
CM_ SG_ 2332164077 I2A_Info4_HW_Ver_Byte10 "IMM硬件版本字节10";
CM_ SG_ 2332164077 I2A_Info4_HW_Ver_Byte11 "IMM硬件版本字节11";
CM_ SG_ 2332164077 I2A_Info4_HW_Ver_Byte12 "IMM硬件版本字节12";
CM_ SG_ 2332164077 I2A_Info4_HW_Ver_Byte13 "IMM硬件版本字节13";
CM_ SG_ 2332164077 I2A_Info4_HW_Ver_Byte14 "IMM硬件版本字节14";
CM_ SG_ 2332164077 I2A_Info4_HW_Ver_Byte15 "IMM硬件版本字节15";
CM_ SG_ 2332164077 I2A_Info4_HW_Ver_Byte16 "IMM硬件版本字节16";
CM_ SG_ 2332164078 I2A_Barcode1 "当前IMM的Barcode1(压缩BCD码）";
CM_ SG_ 2332164078 I2A_Barcode2 "当前IMM的Barcode2(压缩BCD码）";
CM_ SG_ 2332164078 I2A_Barcode3 "当前IMM的Barcode3(压缩BCD码）";
CM_ SG_ 2332164078 I2A_Barcode4 "当前IMM的Barcode4(压缩BCD码）";
CM_ SG_ 2332164078 I2A_Barcode5 "当前IMM的Barcode5(压缩BCD码）";
CM_ SG_ 2332164078 I2A_Barcode6 "当前IMM的Barcode6(压缩BCD码）";
CM_ SG_ 2332164079 I2A_SUMDATA1_CRC "IMM发送的概要数据1的CRC";
CM_ SG_ 2332164079 I2A_SUMDATA1_ALIV "IMM发送的概要数据1的生命信号，0~15循环";
CM_ SG_ 2332164079 I2A_VoltVld "IMM采样有效标志";
CM_ SG_ 2332164079 I2A_VoltErr "IMM板电源故障标志(暂未使用）";
CM_ SG_ 2332164079 I2A_InsResValid "IMM绝缘阻值有效性";
CM_ SG_ 2332164079 I2A_IsoResPos "主正对机壳的有效绝缘阻值";
CM_ SG_ 2332164079 I2A_IsoResNeg "主负对机壳的有效绝缘阻值";
CM_ SG_ 2483137262 P2E_Cfg5_MBMU_CMD "新增功能使用： 0xA0  写入  ，0x50读取；
如果需要写入多报文，使用0xA1，0xA2…";
CM_ SG_ 2483137262 P2E_Cfg5_MBMU_Add "新增功能使用： 功能编码，根据功能定义具含义";
CM_ SG_ 2483137262 P2E_Cfg5_MBMU_data1 "根据功能码定义和解析数据1";
CM_ SG_ 2483137262 P2E_Cfg5_MBMU_data2 "根据功能码定义和解析数据2";
CM_ SG_ 2483137262 P2E_Cfg5_MBMU_data3 "根据功能码定义和解析数据3";
CM_ SG_ 2483137262 P2E_Cfg5_MBMU_data4 "根据功能码定义和解析数据4";
CM_ SG_ 2483137262 P2E_Cfg5_MBMU_data5 "根据功能码定义和解析数据5";
CM_ SG_ 2483137262 P2E_Cfg5_MBMU_data6 "根据功能码定义和解析数据6";
CM_ SG_ 2483220113 E2P_SUMDATA1_Byte1_01 "ETH参数  系统中SBMU数量";
CM_ SG_ 2483220113 E2P_SUMDATA1_Byte2_01 "ETH参数  系统中最小运行SBMU数量";
CM_ SG_ 2483220114 E2P_SUMDATA1_Byte1_02 "ETH参数  系统中SBMU数量";
CM_ SG_ 2483220114 E2P_SUMDATA1_Byte2_02 "ETH参数  系统中最小运行SBMU数量";
CM_ SG_ 2483220115 E2P_SUMDATA1_Byte1_03 "ETH参数  系统中SBMU数量";
CM_ SG_ 2483220115 E2P_SUMDATA1_Byte2_03 "ETH参数  系统中最小运行SBMU数量";
CM_ SG_ 2483220116 E2P_SUMDATA1_Byte1_04 "ETH参数  系统中SBMU数量";
CM_ SG_ 2483220116 E2P_SUMDATA1_Byte2_04 "ETH参数  系统中最小运行SBMU数量";
CM_ SG_ 2483220117 E2P_SUMDATA1_Byte1_05 "ETH参数  系统中SBMU数量";
CM_ SG_ 2483220117 E2P_SUMDATA1_Byte2_05 "ETH参数  系统中最小运行SBMU数量";
CM_ SG_ 2483220118 E2P_SUMDATA1_Byte1_06 "ETH参数  系统中SBMU数量";
CM_ SG_ 2483220118 E2P_SUMDATA1_Byte2_06 "ETH参数  系统中最小运行SBMU数量";
CM_ SG_ 2483220119 E2P_SUMDATA1_Byte1_07 "ETH参数  系统中SBMU数量";
CM_ SG_ 2483220119 E2P_SUMDATA1_Byte2_07 "ETH参数  系统中最小运行SBMU数量";
CM_ SG_ 2483220120 E2P_SUMDATA1_Byte1_08 "ETH参数  系统中SBMU数量";
CM_ SG_ 2483220120 E2P_SUMDATA1_Byte2_08 "ETH参数  系统中最小运行SBMU数量";
CM_ SG_ 2483220121 E2P_SUMDATA1_Byte1_09 "ETH参数  系统中SBMU数量";
CM_ SG_ 2483220121 E2P_SUMDATA1_Byte2_09 "ETH参数  系统中最小运行SBMU数量";
CM_ SG_ 2483220122 E2P_SUMDATA1_Byte1_10 "ETH参数  系统中SBMU数量";
CM_ SG_ 2483220122 E2P_SUMDATA1_Byte2_10 "ETH参数  系统中最小运行SBMU数量";
CM_ SG_ 2483220123 E2P_SUMDATA1_Byte1_11 "ETH参数  系统中SBMU数量";
CM_ SG_ 2483220123 E2P_SUMDATA1_Byte2_11 "ETH参数  系统中最小运行SBMU数量";
CM_ SG_ 2483220124 E2P_SUMDATA1_Byte1_12 "ETH参数  系统中SBMU数量";
CM_ SG_ 2483220124 E2P_SUMDATA1_Byte2_12 "ETH参数  系统中最小运行SBMU数量";
CM_ SG_ 2483220125 E2P_SUMDATA1_Byte1_13 "ETH参数  系统中SBMU数量";
CM_ SG_ 2483220125 E2P_SUMDATA1_Byte2_13 "ETH参数  系统中最小运行SBMU数量";
CM_ SG_ 2483220126 E2P_SUMDATA1_Byte1_14 "ETH参数  系统中SBMU数量";
CM_ SG_ 2483220126 E2P_SUMDATA1_Byte2_14 "ETH参数  系统中最小运行SBMU数量";
CM_ SG_ 2483220127 E2P_SUMDATA1_Byte1_15 "ETH参数  系统中SBMU数量";
CM_ SG_ 2483220127 E2P_SUMDATA1_Byte2_15 "ETH参数  系统中最小运行SBMU数量";
CM_ SG_ 2483220128 E2P_SUMDATA1_Byte1_16 "ETH参数  系统中SBMU数量";
CM_ SG_ 2483220128 E2P_SUMDATA1_Byte2_16 "ETH参数  系统中最小运行SBMU数量";
CM_ SG_ 2483220129 E2P_SUMDATA1_Byte1_17 "ETH参数  系统中SBMU数量";
CM_ SG_ 2483220129 E2P_SUMDATA1_Byte2_17 "ETH参数  系统中最小运行SBMU数量";
CM_ SG_ 2483220130 E2P_SUMDATA1_Byte1_18 "ETH参数  系统中SBMU数量";
CM_ SG_ 2483220130 E2P_SUMDATA1_Byte2_18 "ETH参数  系统中最小运行SBMU数量";
CM_ SG_ 2483220131 E2P_SUMDATA1_Byte1_19 "ETH参数  系统中SBMU数量";
CM_ SG_ 2483220131 E2P_SUMDATA1_Byte2_19 "ETH参数  系统中最小运行SBMU数量";
CM_ SG_ 2483220132 E2P_SUMDATA1_Byte1_20 "ETH参数  系统中SBMU数量";
CM_ SG_ 2483220132 E2P_SUMDATA1_Byte2_20 "ETH参数  系统中最小运行SBMU数量";
CM_ SG_ 2483220133 E2P_SUMDATA1_Byte1_21 "ETH参数  系统中SBMU数量";
CM_ SG_ 2483220133 E2P_SUMDATA1_Byte2_21 "ETH参数  系统中最小运行SBMU数量";
CM_ SG_ 2483220134 E2P_SUMDATA1_Byte1_22 "ETH参数  系统中SBMU数量";
CM_ SG_ 2483220134 E2P_SUMDATA1_Byte2_22 "ETH参数  系统中最小运行SBMU数量";
CM_ SG_ 2483220135 E2P_SUMDATA1_Byte1_23 "ETH参数  系统中SBMU数量";
CM_ SG_ 2483220135 E2P_SUMDATA1_Byte2_23 "ETH参数  系统中最小运行SBMU数量";
CM_ SG_ 2483220136 E2P_SUMDATA1_Byte1_24 "ETH参数  系统中SBMU数量";
CM_ SG_ 2483220136 E2P_SUMDATA1_Byte2_24 "ETH参数  系统中最小运行SBMU数量";
CM_ SG_ 2483220137 E2P_SUMDATA1_Byte1_25 "ETH参数  系统中SBMU数量";
CM_ SG_ 2483220137 E2P_SUMDATA1_Byte2_25 "ETH参数  系统中最小运行SBMU数量";
CM_ SG_ 2483220138 E2P_SUMDATA1_Byte1_26 "ETH参数  系统中SBMU数量";
CM_ SG_ 2483220138 E2P_SUMDATA1_Byte2_26 "ETH参数  系统中最小运行SBMU数量";
CM_ SG_ 2483220139 E2P_SUMDATA1_Byte1_27 "ETH参数  系统中SBMU数量";
CM_ SG_ 2483220139 E2P_SUMDATA1_Byte2_27 "ETH参数  系统中最小运行SBMU数量";
CM_ SG_ 2483220140 E2P_SUMDATA1_Byte1_28 "ETH参数  系统中SBMU数量";
CM_ SG_ 2483220140 E2P_SUMDATA1_Byte2_28 "ETH参数  系统中最小运行SBMU数量";
CM_ SG_ 2483220141 E2P_SUMDATA1_Byte1_29 "ETH参数  系统中SBMU数量";
CM_ SG_ 2483220141 E2P_SUMDATA1_Byte2_29 "ETH参数  系统中最小运行SBMU数量";
CM_ SG_ 2483220142 E2P_SUMDATA1_Byte1_30 "ETH参数  系统中SBMU数量";
CM_ SG_ 2483220142 E2P_SUMDATA1_Byte2_30 "ETH参数  系统中最小运行SBMU数量";
CM_ SG_ 2483220143 E2P_SUMDATA1_Byte1_31 "ETH参数  系统中SBMU数量";
CM_ SG_ 2483220143 E2P_SUMDATA1_Byte2_31 "ETH参数  系统中最小运行SBMU数量";
CM_ SG_ 2483089041 E2P_Response_Byte1_01 "新增功能使用： 0xA0  反馈写入结果  ，0x50反馈读取结果；
如果需要反馈多报文，使用0x51，0x52…";
CM_ SG_ 2483089041 E2P_Response_Byte2_01 "新增功能使用： 功能编码，根据功能定义具含义";
CM_ SG_ 2483089041 E2P_Response_Byte3_01 "根据功能码定义和解析数据1";
CM_ SG_ 2483089041 E2P_Response_Byte4_01 "根据功能码定义和解析数据2";
CM_ SG_ 2483089041 E2P_Response_Byte5_01 "根据功能码定义和解析数据3";
CM_ SG_ 2483089041 E2P_Response_Byte6_01 "根据功能码定义和解析数据4";
CM_ SG_ 2483089041 E2P_Response_Byte7_01 "根据功能码定义和解析数据5";
CM_ SG_ 2483089041 E2P_Response_Byte8_01 "根据功能码定义和解析数据6";
CM_ SG_ 2483089042 E2P_Response_Byte1_02 "新增功能使用： 0xA0  反馈写入结果  ，0x50反馈读取结果；
如果需要反馈多报文，使用0x51，0x52…";
CM_ SG_ 2483089042 E2P_Response_Byte2_02 "新增功能使用： 功能编码，根据功能定义具含义";
CM_ SG_ 2483089042 E2P_Response_Byte3_02 "根据功能码定义和解析数据1";
CM_ SG_ 2483089042 E2P_Response_Byte4_02 "根据功能码定义和解析数据2";
CM_ SG_ 2483089042 E2P_Response_Byte5_02 "根据功能码定义和解析数据3";
CM_ SG_ 2483089042 E2P_Response_Byte6_02 "根据功能码定义和解析数据4";
CM_ SG_ 2483089042 E2P_Response_Byte7_02 "根据功能码定义和解析数据5";
CM_ SG_ 2483089042 E2P_Response_Byte8_02 "根据功能码定义和解析数据6";
CM_ SG_ 2483089043 E2P_Response_Byte1_03 "新增功能使用： 0xA0  反馈写入结果  ，0x50反馈读取结果；
如果需要反馈多报文，使用0x51，0x52…";
CM_ SG_ 2483089043 E2P_Response_Byte2_03 "新增功能使用： 功能编码，根据功能定义具含义";
CM_ SG_ 2483089043 E2P_Response_Byte3_03 "根据功能码定义和解析数据1";
CM_ SG_ 2483089043 E2P_Response_Byte4_03 "根据功能码定义和解析数据2";
CM_ SG_ 2483089043 E2P_Response_Byte5_03 "根据功能码定义和解析数据3";
CM_ SG_ 2483089043 E2P_Response_Byte6_03 "根据功能码定义和解析数据4";
CM_ SG_ 2483089043 E2P_Response_Byte7_03 "根据功能码定义和解析数据5";
CM_ SG_ 2483089043 E2P_Response_Byte8_03 "根据功能码定义和解析数据6";
CM_ SG_ 2483089044 E2P_Response_Byte1_04 "新增功能使用： 0xA0  反馈写入结果  ，0x50反馈读取结果；
如果需要反馈多报文，使用0x51，0x52…";
CM_ SG_ 2483089044 E2P_Response_Byte2_04 "新增功能使用： 功能编码，根据功能定义具含义";
CM_ SG_ 2483089044 E2P_Response_Byte3_04 "根据功能码定义和解析数据1";
CM_ SG_ 2483089044 E2P_Response_Byte4_04 "根据功能码定义和解析数据2";
CM_ SG_ 2483089044 E2P_Response_Byte5_04 "根据功能码定义和解析数据3";
CM_ SG_ 2483089044 E2P_Response_Byte6_04 "根据功能码定义和解析数据4";
CM_ SG_ 2483089044 E2P_Response_Byte7_04 "根据功能码定义和解析数据5";
CM_ SG_ 2483089044 E2P_Response_Byte8_04 "根据功能码定义和解析数据6";
CM_ SG_ 2483089045 E2P_Response_Byte1_05 "新增功能使用： 0xA0  反馈写入结果  ，0x50反馈读取结果；
如果需要反馈多报文，使用0x51，0x52…";
CM_ SG_ 2483089045 E2P_Response_Byte2_05 "新增功能使用： 功能编码，根据功能定义具含义";
CM_ SG_ 2483089045 E2P_Response_Byte3_05 "根据功能码定义和解析数据1";
CM_ SG_ 2483089045 E2P_Response_Byte4_05 "根据功能码定义和解析数据2";
CM_ SG_ 2483089045 E2P_Response_Byte5_05 "根据功能码定义和解析数据3";
CM_ SG_ 2483089045 E2P_Response_Byte6_05 "根据功能码定义和解析数据4";
CM_ SG_ 2483089045 E2P_Response_Byte7_05 "根据功能码定义和解析数据5";
CM_ SG_ 2483089045 E2P_Response_Byte8_05 "根据功能码定义和解析数据6";
CM_ SG_ 2483089046 E2P_Response_Byte1_06 "新增功能使用： 0xA0  反馈写入结果  ，0x50反馈读取结果；
如果需要反馈多报文，使用0x51，0x52…";
CM_ SG_ 2483089046 E2P_Response_Byte2_06 "新增功能使用： 功能编码，根据功能定义具含义";
CM_ SG_ 2483089046 E2P_Response_Byte3_06 "根据功能码定义和解析数据1";
CM_ SG_ 2483089046 E2P_Response_Byte4_06 "根据功能码定义和解析数据2";
CM_ SG_ 2483089046 E2P_Response_Byte5_06 "根据功能码定义和解析数据3";
CM_ SG_ 2483089046 E2P_Response_Byte6_06 "根据功能码定义和解析数据4";
CM_ SG_ 2483089046 E2P_Response_Byte7_06 "根据功能码定义和解析数据5";
CM_ SG_ 2483089046 E2P_Response_Byte8_06 "根据功能码定义和解析数据6";
CM_ SG_ 2483089047 E2P_Response_Byte1_07 "新增功能使用： 0xA0  反馈写入结果  ，0x50反馈读取结果；
如果需要反馈多报文，使用0x51，0x52…";
CM_ SG_ 2483089047 E2P_Response_Byte2_07 "新增功能使用： 功能编码，根据功能定义具含义";
CM_ SG_ 2483089047 E2P_Response_Byte3_07 "根据功能码定义和解析数据1";
CM_ SG_ 2483089047 E2P_Response_Byte4_07 "根据功能码定义和解析数据2";
CM_ SG_ 2483089047 E2P_Response_Byte5_07 "根据功能码定义和解析数据3";
CM_ SG_ 2483089047 E2P_Response_Byte6_07 "根据功能码定义和解析数据4";
CM_ SG_ 2483089047 E2P_Response_Byte7_07 "根据功能码定义和解析数据5";
CM_ SG_ 2483089047 E2P_Response_Byte8_07 "根据功能码定义和解析数据6";
CM_ SG_ 2483089048 E2P_Response_Byte1_08 "新增功能使用： 0xA0  反馈写入结果  ，0x50反馈读取结果；
如果需要反馈多报文，使用0x51，0x52…";
CM_ SG_ 2483089048 E2P_Response_Byte2_08 "新增功能使用： 功能编码，根据功能定义具含义";
CM_ SG_ 2483089048 E2P_Response_Byte3_08 "根据功能码定义和解析数据1";
CM_ SG_ 2483089048 E2P_Response_Byte4_08 "根据功能码定义和解析数据2";
CM_ SG_ 2483089048 E2P_Response_Byte5_08 "根据功能码定义和解析数据3";
CM_ SG_ 2483089048 E2P_Response_Byte6_08 "根据功能码定义和解析数据4";
CM_ SG_ 2483089048 E2P_Response_Byte7_08 "根据功能码定义和解析数据5";
CM_ SG_ 2483089048 E2P_Response_Byte8_08 "根据功能码定义和解析数据6";
CM_ SG_ 2483089049 E2P_Response_Byte1_09 "新增功能使用： 0xA0  反馈写入结果  ，0x50反馈读取结果；
如果需要反馈多报文，使用0x51，0x52…";
CM_ SG_ 2483089049 E2P_Response_Byte2_09 "新增功能使用： 功能编码，根据功能定义具含义";
CM_ SG_ 2483089049 E2P_Response_Byte3_09 "根据功能码定义和解析数据1";
CM_ SG_ 2483089049 E2P_Response_Byte4_09 "根据功能码定义和解析数据2";
CM_ SG_ 2483089049 E2P_Response_Byte5_09 "根据功能码定义和解析数据3";
CM_ SG_ 2483089049 E2P_Response_Byte6_09 "根据功能码定义和解析数据4";
CM_ SG_ 2483089049 E2P_Response_Byte7_09 "根据功能码定义和解析数据5";
CM_ SG_ 2483089049 E2P_Response_Byte8_09 "根据功能码定义和解析数据6";
CM_ SG_ 2483089050 E2P_Response_Byte1_10 "新增功能使用： 0xA0  反馈写入结果  ，0x50反馈读取结果；
如果需要反馈多报文，使用0x51，0x52…";
CM_ SG_ 2483089050 E2P_Response_Byte2_10 "新增功能使用： 功能编码，根据功能定义具含义";
CM_ SG_ 2483089050 E2P_Response_Byte3_10 "根据功能码定义和解析数据1";
CM_ SG_ 2483089050 E2P_Response_Byte4_10 "根据功能码定义和解析数据2";
CM_ SG_ 2483089050 E2P_Response_Byte5_10 "根据功能码定义和解析数据3";
CM_ SG_ 2483089050 E2P_Response_Byte6_10 "根据功能码定义和解析数据4";
CM_ SG_ 2483089050 E2P_Response_Byte7_10 "根据功能码定义和解析数据5";
CM_ SG_ 2483089050 E2P_Response_Byte8_10 "根据功能码定义和解析数据6";
CM_ SG_ 2483089051 E2P_Response_Byte1_11 "新增功能使用： 0xA0  反馈写入结果  ，0x50反馈读取结果；
如果需要反馈多报文，使用0x51，0x52…";
CM_ SG_ 2483089051 E2P_Response_Byte2_11 "新增功能使用： 功能编码，根据功能定义具含义";
CM_ SG_ 2483089051 E2P_Response_Byte3_11 "根据功能码定义和解析数据1";
CM_ SG_ 2483089051 E2P_Response_Byte4_11 "根据功能码定义和解析数据2";
CM_ SG_ 2483089051 E2P_Response_Byte5_11 "根据功能码定义和解析数据3";
CM_ SG_ 2483089051 E2P_Response_Byte6_11 "根据功能码定义和解析数据4";
CM_ SG_ 2483089051 E2P_Response_Byte7_11 "根据功能码定义和解析数据5";
CM_ SG_ 2483089051 E2P_Response_Byte8_11 "根据功能码定义和解析数据6";
CM_ SG_ 2483089052 E2P_Response_Byte1_12 "新增功能使用： 0xA0  反馈写入结果  ，0x50反馈读取结果；
如果需要反馈多报文，使用0x51，0x52…";
CM_ SG_ 2483089052 E2P_Response_Byte2_12 "新增功能使用： 功能编码，根据功能定义具含义";
CM_ SG_ 2483089052 E2P_Response_Byte3_12 "根据功能码定义和解析数据1";
CM_ SG_ 2483089052 E2P_Response_Byte4_12 "根据功能码定义和解析数据2";
CM_ SG_ 2483089052 E2P_Response_Byte5_12 "根据功能码定义和解析数据3";
CM_ SG_ 2483089052 E2P_Response_Byte6_12 "根据功能码定义和解析数据4";
CM_ SG_ 2483089052 E2P_Response_Byte7_12 "根据功能码定义和解析数据5";
CM_ SG_ 2483089052 E2P_Response_Byte8_12 "根据功能码定义和解析数据6";
CM_ SG_ 2483089053 E2P_Response_Byte1_13 "新增功能使用： 0xA0  反馈写入结果  ，0x50反馈读取结果；
如果需要反馈多报文，使用0x51，0x52…";
CM_ SG_ 2483089053 E2P_Response_Byte2_13 "新增功能使用： 功能编码，根据功能定义具含义";
CM_ SG_ 2483089053 E2P_Response_Byte3_13 "根据功能码定义和解析数据1";
CM_ SG_ 2483089053 E2P_Response_Byte4_13 "根据功能码定义和解析数据2";
CM_ SG_ 2483089053 E2P_Response_Byte5_13 "根据功能码定义和解析数据3";
CM_ SG_ 2483089053 E2P_Response_Byte6_13 "根据功能码定义和解析数据4";
CM_ SG_ 2483089053 E2P_Response_Byte7_13 "根据功能码定义和解析数据5";
CM_ SG_ 2483089053 E2P_Response_Byte8_13 "根据功能码定义和解析数据6";
CM_ SG_ 2483089054 E2P_Response_Byte1_14 "新增功能使用： 0xA0  反馈写入结果  ，0x50反馈读取结果；
如果需要反馈多报文，使用0x51，0x52…";
CM_ SG_ 2483089054 E2P_Response_Byte2_14 "新增功能使用： 功能编码，根据功能定义具含义";
CM_ SG_ 2483089054 E2P_Response_Byte3_14 "根据功能码定义和解析数据1";
CM_ SG_ 2483089054 E2P_Response_Byte4_14 "根据功能码定义和解析数据2";
CM_ SG_ 2483089054 E2P_Response_Byte5_14 "根据功能码定义和解析数据3";
CM_ SG_ 2483089054 E2P_Response_Byte6_14 "根据功能码定义和解析数据4";
CM_ SG_ 2483089054 E2P_Response_Byte7_14 "根据功能码定义和解析数据5";
CM_ SG_ 2483089054 E2P_Response_Byte8_14 "根据功能码定义和解析数据6";
CM_ SG_ 2483089055 E2P_Response_Byte1_15 "新增功能使用： 0xA0  反馈写入结果  ，0x50反馈读取结果；
如果需要反馈多报文，使用0x51，0x52…";
CM_ SG_ 2483089055 E2P_Response_Byte2_15 "新增功能使用： 功能编码，根据功能定义具含义";
CM_ SG_ 2483089055 E2P_Response_Byte3_15 "根据功能码定义和解析数据1";
CM_ SG_ 2483089055 E2P_Response_Byte4_15 "根据功能码定义和解析数据2";
CM_ SG_ 2483089055 E2P_Response_Byte5_15 "根据功能码定义和解析数据3";
CM_ SG_ 2483089055 E2P_Response_Byte6_15 "根据功能码定义和解析数据4";
CM_ SG_ 2483089055 E2P_Response_Byte7_15 "根据功能码定义和解析数据5";
CM_ SG_ 2483089055 E2P_Response_Byte8_15 "根据功能码定义和解析数据6";
CM_ SG_ 2483089056 E2P_Response_Byte1_16 "新增功能使用： 0xA0  反馈写入结果  ，0x50反馈读取结果；
如果需要反馈多报文，使用0x51，0x52…";
CM_ SG_ 2483089056 E2P_Response_Byte2_16 "新增功能使用： 功能编码，根据功能定义具含义";
CM_ SG_ 2483089056 E2P_Response_Byte3_16 "根据功能码定义和解析数据1";
CM_ SG_ 2483089056 E2P_Response_Byte4_16 "根据功能码定义和解析数据2";
CM_ SG_ 2483089056 E2P_Response_Byte5_16 "根据功能码定义和解析数据3";
CM_ SG_ 2483089056 E2P_Response_Byte6_16 "根据功能码定义和解析数据4";
CM_ SG_ 2483089056 E2P_Response_Byte7_16 "根据功能码定义和解析数据5";
CM_ SG_ 2483089056 E2P_Response_Byte8_16 "根据功能码定义和解析数据6";
CM_ SG_ 2483089057 E2P_Response_Byte1_17 "新增功能使用： 0xA0  反馈写入结果  ，0x50反馈读取结果；
如果需要反馈多报文，使用0x51，0x52…";
CM_ SG_ 2483089057 E2P_Response_Byte2_17 "新增功能使用： 功能编码，根据功能定义具含义";
CM_ SG_ 2483089057 E2P_Response_Byte3_17 "根据功能码定义和解析数据1";
CM_ SG_ 2483089057 E2P_Response_Byte4_17 "根据功能码定义和解析数据2";
CM_ SG_ 2483089057 E2P_Response_Byte5_17 "根据功能码定义和解析数据3";
CM_ SG_ 2483089057 E2P_Response_Byte6_17 "根据功能码定义和解析数据4";
CM_ SG_ 2483089057 E2P_Response_Byte7_17 "根据功能码定义和解析数据5";
CM_ SG_ 2483089057 E2P_Response_Byte8_17 "根据功能码定义和解析数据6";
CM_ SG_ 2483089058 E2P_Response_Byte1_18 "新增功能使用： 0xA0  反馈写入结果  ，0x50反馈读取结果；
如果需要反馈多报文，使用0x51，0x52…";
CM_ SG_ 2483089058 E2P_Response_Byte2_18 "新增功能使用： 功能编码，根据功能定义具含义";
CM_ SG_ 2483089058 E2P_Response_Byte3_18 "根据功能码定义和解析数据1";
CM_ SG_ 2483089058 E2P_Response_Byte4_18 "根据功能码定义和解析数据2";
CM_ SG_ 2483089058 E2P_Response_Byte5_18 "根据功能码定义和解析数据3";
CM_ SG_ 2483089058 E2P_Response_Byte6_18 "根据功能码定义和解析数据4";
CM_ SG_ 2483089058 E2P_Response_Byte7_18 "根据功能码定义和解析数据5";
CM_ SG_ 2483089058 E2P_Response_Byte8_18 "根据功能码定义和解析数据6";
CM_ SG_ 2483089059 E2P_Response_Byte1_19 "新增功能使用： 0xA0  反馈写入结果  ，0x50反馈读取结果；
如果需要反馈多报文，使用0x51，0x52…";
CM_ SG_ 2483089059 E2P_Response_Byte2_19 "新增功能使用： 功能编码，根据功能定义具含义";
CM_ SG_ 2483089059 E2P_Response_Byte3_19 "根据功能码定义和解析数据1";
CM_ SG_ 2483089059 E2P_Response_Byte4_19 "根据功能码定义和解析数据2";
CM_ SG_ 2483089059 E2P_Response_Byte5_19 "根据功能码定义和解析数据3";
CM_ SG_ 2483089059 E2P_Response_Byte6_19 "根据功能码定义和解析数据4";
CM_ SG_ 2483089059 E2P_Response_Byte7_19 "根据功能码定义和解析数据5";
CM_ SG_ 2483089059 E2P_Response_Byte8_19 "根据功能码定义和解析数据6";
CM_ SG_ 2483089060 E2P_Response_Byte1_20 "新增功能使用： 0xA0  反馈写入结果  ，0x50反馈读取结果；
如果需要反馈多报文，使用0x51，0x52…";
CM_ SG_ 2483089060 E2P_Response_Byte2_20 "新增功能使用： 功能编码，根据功能定义具含义";
CM_ SG_ 2483089060 E2P_Response_Byte3_20 "根据功能码定义和解析数据1";
CM_ SG_ 2483089060 E2P_Response_Byte4_20 "根据功能码定义和解析数据2";
CM_ SG_ 2483089060 E2P_Response_Byte5_20 "根据功能码定义和解析数据3";
CM_ SG_ 2483089060 E2P_Response_Byte6_20 "根据功能码定义和解析数据4";
CM_ SG_ 2483089060 E2P_Response_Byte7_20 "根据功能码定义和解析数据5";
CM_ SG_ 2483089060 E2P_Response_Byte8_20 "根据功能码定义和解析数据6";
CM_ SG_ 2483089061 E2P_Response_Byte1_21 "新增功能使用： 0xA0  反馈写入结果  ，0x50反馈读取结果；
如果需要反馈多报文，使用0x51，0x52…";
CM_ SG_ 2483089061 E2P_Response_Byte2_21 "新增功能使用： 功能编码，根据功能定义具含义";
CM_ SG_ 2483089061 E2P_Response_Byte3_21 "根据功能码定义和解析数据1";
CM_ SG_ 2483089061 E2P_Response_Byte4_21 "根据功能码定义和解析数据2";
CM_ SG_ 2483089061 E2P_Response_Byte5_21 "根据功能码定义和解析数据3";
CM_ SG_ 2483089061 E2P_Response_Byte6_21 "根据功能码定义和解析数据4";
CM_ SG_ 2483089061 E2P_Response_Byte7_21 "根据功能码定义和解析数据5";
CM_ SG_ 2483089061 E2P_Response_Byte8_21 "根据功能码定义和解析数据6";
CM_ SG_ 2483089062 E2P_Response_Byte1_22 "新增功能使用： 0xA0  反馈写入结果  ，0x50反馈读取结果；
如果需要反馈多报文，使用0x51，0x52…";
CM_ SG_ 2483089062 E2P_Response_Byte2_22 "新增功能使用： 功能编码，根据功能定义具含义";
CM_ SG_ 2483089062 E2P_Response_Byte3_22 "根据功能码定义和解析数据1";
CM_ SG_ 2483089062 E2P_Response_Byte4_22 "根据功能码定义和解析数据2";
CM_ SG_ 2483089062 E2P_Response_Byte5_22 "根据功能码定义和解析数据3";
CM_ SG_ 2483089062 E2P_Response_Byte6_22 "根据功能码定义和解析数据4";
CM_ SG_ 2483089062 E2P_Response_Byte7_22 "根据功能码定义和解析数据5";
CM_ SG_ 2483089062 E2P_Response_Byte8_22 "根据功能码定义和解析数据6";
CM_ SG_ 2483089063 E2P_Response_Byte1_23 "新增功能使用： 0xA0  反馈写入结果  ，0x50反馈读取结果；
如果需要反馈多报文，使用0x51，0x52…";
CM_ SG_ 2483089063 E2P_Response_Byte2_23 "新增功能使用： 功能编码，根据功能定义具含义";
CM_ SG_ 2483089063 E2P_Response_Byte3_23 "根据功能码定义和解析数据1";
CM_ SG_ 2483089063 E2P_Response_Byte4_23 "根据功能码定义和解析数据2";
CM_ SG_ 2483089063 E2P_Response_Byte5_23 "根据功能码定义和解析数据3";
CM_ SG_ 2483089063 E2P_Response_Byte6_23 "根据功能码定义和解析数据4";
CM_ SG_ 2483089063 E2P_Response_Byte7_23 "根据功能码定义和解析数据5";
CM_ SG_ 2483089063 E2P_Response_Byte8_23 "根据功能码定义和解析数据6";
CM_ SG_ 2483089064 E2P_Response_Byte1_24 "新增功能使用： 0xA0  反馈写入结果  ，0x50反馈读取结果；
如果需要反馈多报文，使用0x51，0x52…";
CM_ SG_ 2483089064 E2P_Response_Byte2_24 "新增功能使用： 功能编码，根据功能定义具含义";
CM_ SG_ 2483089064 E2P_Response_Byte3_24 "根据功能码定义和解析数据1";
CM_ SG_ 2483089064 E2P_Response_Byte4_24 "根据功能码定义和解析数据2";
CM_ SG_ 2483089064 E2P_Response_Byte5_24 "根据功能码定义和解析数据3";
CM_ SG_ 2483089064 E2P_Response_Byte6_24 "根据功能码定义和解析数据4";
CM_ SG_ 2483089064 E2P_Response_Byte7_24 "根据功能码定义和解析数据5";
CM_ SG_ 2483089064 E2P_Response_Byte8_24 "根据功能码定义和解析数据6";
CM_ SG_ 2483089065 E2P_Response_Byte1_25 "新增功能使用： 0xA0  反馈写入结果  ，0x50反馈读取结果；
如果需要反馈多报文，使用0x51，0x52…";
CM_ SG_ 2483089065 E2P_Response_Byte2_25 "新增功能使用： 功能编码，根据功能定义具含义";
CM_ SG_ 2483089065 E2P_Response_Byte3_25 "根据功能码定义和解析数据1";
CM_ SG_ 2483089065 E2P_Response_Byte4_25 "根据功能码定义和解析数据2";
CM_ SG_ 2483089065 E2P_Response_Byte5_25 "根据功能码定义和解析数据3";
CM_ SG_ 2483089065 E2P_Response_Byte6_25 "根据功能码定义和解析数据4";
CM_ SG_ 2483089065 E2P_Response_Byte7_25 "根据功能码定义和解析数据5";
CM_ SG_ 2483089065 E2P_Response_Byte8_25 "根据功能码定义和解析数据6";
CM_ SG_ 2483089066 E2P_Response_Byte1_26 "新增功能使用： 0xA0  反馈写入结果  ，0x50反馈读取结果；
如果需要反馈多报文，使用0x51，0x52…";
CM_ SG_ 2483089066 E2P_Response_Byte2_26 "新增功能使用： 功能编码，根据功能定义具含义";
CM_ SG_ 2483089066 E2P_Response_Byte3_26 "根据功能码定义和解析数据1";
CM_ SG_ 2483089066 E2P_Response_Byte4_26 "根据功能码定义和解析数据2";
CM_ SG_ 2483089066 E2P_Response_Byte5_26 "根据功能码定义和解析数据3";
CM_ SG_ 2483089066 E2P_Response_Byte6_26 "根据功能码定义和解析数据4";
CM_ SG_ 2483089066 E2P_Response_Byte7_26 "根据功能码定义和解析数据5";
CM_ SG_ 2483089066 E2P_Response_Byte8_26 "根据功能码定义和解析数据6";
CM_ SG_ 2483089067 E2P_Response_Byte1_27 "新增功能使用： 0xA0  反馈写入结果  ，0x50反馈读取结果；
如果需要反馈多报文，使用0x51，0x52…";
CM_ SG_ 2483089067 E2P_Response_Byte2_27 "新增功能使用： 功能编码，根据功能定义具含义";
CM_ SG_ 2483089067 E2P_Response_Byte3_27 "根据功能码定义和解析数据1";
CM_ SG_ 2483089067 E2P_Response_Byte4_27 "根据功能码定义和解析数据2";
CM_ SG_ 2483089067 E2P_Response_Byte5_27 "根据功能码定义和解析数据3";
CM_ SG_ 2483089067 E2P_Response_Byte6_27 "根据功能码定义和解析数据4";
CM_ SG_ 2483089067 E2P_Response_Byte7_27 "根据功能码定义和解析数据5";
CM_ SG_ 2483089067 E2P_Response_Byte8_27 "根据功能码定义和解析数据6";
CM_ SG_ 2483089068 E2P_Response_Byte1_28 "新增功能使用： 0xA0  反馈写入结果  ，0x50反馈读取结果；
如果需要反馈多报文，使用0x51，0x52…";
CM_ SG_ 2483089068 E2P_Response_Byte2_28 "新增功能使用： 功能编码，根据功能定义具含义";
CM_ SG_ 2483089068 E2P_Response_Byte3_28 "根据功能码定义和解析数据1";
CM_ SG_ 2483089068 E2P_Response_Byte4_28 "根据功能码定义和解析数据2";
CM_ SG_ 2483089068 E2P_Response_Byte5_28 "根据功能码定义和解析数据3";
CM_ SG_ 2483089068 E2P_Response_Byte6_28 "根据功能码定义和解析数据4";
CM_ SG_ 2483089068 E2P_Response_Byte7_28 "根据功能码定义和解析数据5";
CM_ SG_ 2483089068 E2P_Response_Byte8_28 "根据功能码定义和解析数据6";
CM_ SG_ 2483089069 E2P_Response_Byte1_29 "新增功能使用： 0xA0  反馈写入结果  ，0x50反馈读取结果；
如果需要反馈多报文，使用0x51，0x52…";
CM_ SG_ 2483089069 E2P_Response_Byte2_29 "新增功能使用： 功能编码，根据功能定义具含义";
CM_ SG_ 2483089069 E2P_Response_Byte3_29 "根据功能码定义和解析数据1";
CM_ SG_ 2483089069 E2P_Response_Byte4_29 "根据功能码定义和解析数据2";
CM_ SG_ 2483089069 E2P_Response_Byte5_29 "根据功能码定义和解析数据3";
CM_ SG_ 2483089069 E2P_Response_Byte6_29 "根据功能码定义和解析数据4";
CM_ SG_ 2483089069 E2P_Response_Byte7_29 "根据功能码定义和解析数据5";
CM_ SG_ 2483089069 E2P_Response_Byte8_29 "根据功能码定义和解析数据6";
CM_ SG_ 2483089070 E2P_Response_Byte1_30 "新增功能使用： 0xA0  反馈写入结果  ，0x50反馈读取结果；
如果需要反馈多报文，使用0x51，0x52…";
CM_ SG_ 2483089070 E2P_Response_Byte2_30 "新增功能使用： 功能编码，根据功能定义具含义";
CM_ SG_ 2483089070 E2P_Response_Byte3_30 "根据功能码定义和解析数据1";
CM_ SG_ 2483089070 E2P_Response_Byte4_30 "根据功能码定义和解析数据2";
CM_ SG_ 2483089070 E2P_Response_Byte5_30 "根据功能码定义和解析数据3";
CM_ SG_ 2483089070 E2P_Response_Byte6_30 "根据功能码定义和解析数据4";
CM_ SG_ 2483089070 E2P_Response_Byte7_30 "根据功能码定义和解析数据5";
CM_ SG_ 2483089070 E2P_Response_Byte8_30 "根据功能码定义和解析数据6";
CM_ SG_ 2483089071 E2P_Response_Byte1_31 "新增功能使用： 0xA0  反馈写入结果  ，0x50反馈读取结果；
如果需要反馈多报文，使用0x51，0x52…";
CM_ SG_ 2483089071 E2P_Response_Byte2_31 "新增功能使用： 功能编码，根据功能定义具含义";
CM_ SG_ 2483089071 E2P_Response_Byte3_31 "根据功能码定义和解析数据1";
CM_ SG_ 2483089071 E2P_Response_Byte4_31 "根据功能码定义和解析数据2";
CM_ SG_ 2483089071 E2P_Response_Byte5_31 "根据功能码定义和解析数据3";
CM_ SG_ 2483089071 E2P_Response_Byte6_31 "根据功能码定义和解析数据4";
CM_ SG_ 2483089071 E2P_Response_Byte7_31 "根据功能码定义和解析数据5";
CM_ SG_ 2483089071 E2P_Response_Byte8_31 "根据功能码定义和解析数据6";
CM_ SG_ 2148826945 M2D_CMD1_CRC_01 "CRC校验";
CM_ SG_ 2148826945 M2D_CMD1_DCDCSerialNum_01 "预留  （DCDC编号）";
CM_ SG_ 2148826945 M2D_CMD1_DCDCEnable_01 "使能DCDC命令";
CM_ SG_ 2148826945 M2D_CMD1_Reserved1_01 "预留1";
CM_ SG_ 2148826945 M2D_CMD1_DCDCWrkMdSwtch_01 "DCDC工作状态切换";
CM_ SG_ 2148826945 M2D_CMD1_DCDCWrkMdSet_01 "DCDC工作模式设定";
CM_ SG_ 2148826945 M2D_CMD1_Reserved2_01 "预留2";
CM_ SG_ 2148826945 M2D_CMD1_DCDCOutputCrrntSet_01 "电池电流设定（放正充负）
电池电流=DC低压端电流+DC高压端电流";
CM_ SG_ 2148826945 M2D_CMD1_DCDCOutputVltge_Set_01 "DCDC输出电压设定";
CM_ SG_ 2148826945 M2D_CMD1_Reserved3_01 "预留3";
CM_ SG_ 2148826945 M2D_CMD1_CommunicationState_01 "MBMU与DCDC通讯状态";
CM_ SG_ 2148826945 M2D_CMD1_DCDCFaultClear_01 "DCDC故障清除指令";
CM_ SG_ 2148826945 M2D_CMD1_PCSOperationState_01 "PCS运行状态（预留）";
CM_ SG_ 2148826945 M2D_CMD1_DCDCLVoffControl_01 "DCDC低压下电控制";
CM_ SG_ 2148826945 M2D_CMD1_Reserved4_01 "预留4";
CM_ SG_ 2148826946 M2D_CMD1_CRC_02 "CRC校验";
CM_ SG_ 2148826946 M2D_CMD1_DCDCSerialNum_02 "预留  （DCDC编号）";
CM_ SG_ 2148826946 M2D_CMD1_DCDCEnable_02 "使能DCDC命令";
CM_ SG_ 2148826946 M2D_CMD1_Reserved1_02 "预留1";
CM_ SG_ 2148826946 M2D_CMD1_DCDCWrkMdSwtch_02 "DCDC工作状态切换";
CM_ SG_ 2148826946 M2D_CMD1_DCDCWrkMdSet_02 "DCDC工作模式设定";
CM_ SG_ 2148826946 M2D_CMD1_Reserved2_02 "预留2";
CM_ SG_ 2148826946 M2D_CMD1_DCDCOutputCrrntSet_02 "电池电流设定（放正充负）
电池电流=DC低压端电流+DC高压端电流";
CM_ SG_ 2148826946 M2D_CMD1_DCDCOutputVltge_Set_02 "DCDC输出电压设定";
CM_ SG_ 2148826946 M2D_CMD1_Reserved3_02 "预留3";
CM_ SG_ 2148826946 M2D_CMD1_CommunicationState_02 "MBMU与DCDC通讯状态";
CM_ SG_ 2148826946 M2D_CMD1_DCDCFaultClear_02 "DCDC故障清除指令";
CM_ SG_ 2148826946 M2D_CMD1_PCSOperationState_02 "PCS运行状态（预留）";
CM_ SG_ 2148826946 M2D_CMD1_DCDCLVoffControl_02 "DCDC低压下电控制";
CM_ SG_ 2148826946 M2D_CMD1_Reserved4_02 "预留4";
CM_ SG_ 2148826947 M2D_CMD1_CRC_03 "CRC校验";
CM_ SG_ 2148826947 M2D_CMD1_DCDCSerialNum_03 "预留  （DCDC编号）";
CM_ SG_ 2148826947 M2D_CMD1_DCDCEnable_03 "使能DCDC命令";
CM_ SG_ 2148826947 M2D_CMD1_Reserved1_03 "预留1";
CM_ SG_ 2148826947 M2D_CMD1_DCDCWrkMdSwtch_03 "DCDC工作状态切换";
CM_ SG_ 2148826947 M2D_CMD1_DCDCWrkMdSet_03 "DCDC工作模式设定";
CM_ SG_ 2148826947 M2D_CMD1_Reserved2_03 "预留2";
CM_ SG_ 2148826947 M2D_CMD1_DCDCOutputCrrntSet_03 "电池电流设定（放正充负）
电池电流=DC低压端电流+DC高压端电流";
CM_ SG_ 2148826947 M2D_CMD1_DCDCOutputVltge_Set_03 "DCDC输出电压设定";
CM_ SG_ 2148826947 M2D_CMD1_Reserved3_03 "预留3";
CM_ SG_ 2148826947 M2D_CMD1_CommunicationState_03 "MBMU与DCDC通讯状态";
CM_ SG_ 2148826947 M2D_CMD1_DCDCFaultClear_03 "DCDC故障清除指令";
CM_ SG_ 2148826947 M2D_CMD1_PCSOperationState_03 "PCS运行状态（预留）";
CM_ SG_ 2148826947 M2D_CMD1_DCDCLVoffControl_03 "DCDC低压下电控制";
CM_ SG_ 2148826947 M2D_CMD1_Reserved4_03 "预留4";
CM_ SG_ 2148826948 M2D_CMD1_CRC_04 "CRC校验";
CM_ SG_ 2148826948 M2D_CMD1_DCDCSerialNum_04 "预留  （DCDC编号）";
CM_ SG_ 2148826948 M2D_CMD1_DCDCEnable_04 "使能DCDC命令";
CM_ SG_ 2148826948 M2D_CMD1_Reserved1_04 "预留1";
CM_ SG_ 2148826948 M2D_CMD1_DCDCWrkMdSwtch_04 "DCDC工作状态切换";
CM_ SG_ 2148826948 M2D_CMD1_DCDCWrkMdSet_04 "DCDC工作模式设定";
CM_ SG_ 2148826948 M2D_CMD1_Reserved2_04 "预留2";
CM_ SG_ 2148826948 M2D_CMD1_DCDCOutputCrrntSet_04 "电池电流设定（放正充负）
电池电流=DC低压端电流+DC高压端电流";
CM_ SG_ 2148826948 M2D_CMD1_DCDCOutputVltge_Set_04 "DCDC输出电压设定";
CM_ SG_ 2148826948 M2D_CMD1_Reserved3_04 "预留3";
CM_ SG_ 2148826948 M2D_CMD1_CommunicationState_04 "MBMU与DCDC通讯状态";
CM_ SG_ 2148826948 M2D_CMD1_DCDCFaultClear_04 "DCDC故障清除指令";
CM_ SG_ 2148826948 M2D_CMD1_PCSOperationState_04 "PCS运行状态（预留）";
CM_ SG_ 2148826948 M2D_CMD1_DCDCLVoffControl_04 "DCDC低压下电控制";
CM_ SG_ 2148826948 M2D_CMD1_Reserved4_04 "预留4";
CM_ SG_ 2148826949 M2D_CMD1_CRC_05 "CRC校验";
CM_ SG_ 2148826949 M2D_CMD1_DCDCSerialNum_05 "预留  （DCDC编号）";
CM_ SG_ 2148826949 M2D_CMD1_DCDCEnable_05 "使能DCDC命令";
CM_ SG_ 2148826949 M2D_CMD1_Reserved1_05 "预留1";
CM_ SG_ 2148826949 M2D_CMD1_DCDCWrkMdSwtch_05 "DCDC工作状态切换";
CM_ SG_ 2148826949 M2D_CMD1_DCDCWrkMdSet_05 "DCDC工作模式设定";
CM_ SG_ 2148826949 M2D_CMD1_Reserved2_05 "预留2";
CM_ SG_ 2148826949 M2D_CMD1_DCDCOutputCrrntSet_05 "电池电流设定（放正充负）
电池电流=DC低压端电流+DC高压端电流";
CM_ SG_ 2148826949 M2D_CMD1_DCDCOutputVltge_Set_05 "DCDC输出电压设定";
CM_ SG_ 2148826949 M2D_CMD1_Reserved3_05 "预留3";
CM_ SG_ 2148826949 M2D_CMD1_CommunicationState_05 "MBMU与DCDC通讯状态";
CM_ SG_ 2148826949 M2D_CMD1_DCDCFaultClear_05 "DCDC故障清除指令";
CM_ SG_ 2148826949 M2D_CMD1_PCSOperationState_05 "PCS运行状态（预留）";
CM_ SG_ 2148826949 M2D_CMD1_DCDCLVoffControl_05 "DCDC低压下电控制";
CM_ SG_ 2148826949 M2D_CMD1_Reserved4_05 "预留4";
CM_ SG_ 2148826950 M2D_CMD1_CRC_06 "CRC校验";
CM_ SG_ 2148826950 M2D_CMD1_DCDCSerialNum_06 "预留  （DCDC编号）";
CM_ SG_ 2148826950 M2D_CMD1_DCDCEnable_06 "使能DCDC命令";
CM_ SG_ 2148826950 M2D_CMD1_Reserved1_06 "预留1";
CM_ SG_ 2148826950 M2D_CMD1_DCDCWrkMdSwtch_06 "DCDC工作状态切换";
CM_ SG_ 2148826950 M2D_CMD1_DCDCWrkMdSet_06 "DCDC工作模式设定";
CM_ SG_ 2148826950 M2D_CMD1_Reserved2_06 "预留2";
CM_ SG_ 2148826950 M2D_CMD1_DCDCOutputCrrntSet_06 "电池电流设定（放正充负）
电池电流=DC低压端电流+DC高压端电流";
CM_ SG_ 2148826950 M2D_CMD1_DCDCOutputVltge_Set_06 "DCDC输出电压设定";
CM_ SG_ 2148826950 M2D_CMD1_Reserved3_06 "预留3";
CM_ SG_ 2148826950 M2D_CMD1_CommunicationState_06 "MBMU与DCDC通讯状态";
CM_ SG_ 2148826950 M2D_CMD1_DCDCFaultClear_06 "DCDC故障清除指令";
CM_ SG_ 2148826950 M2D_CMD1_PCSOperationState_06 "PCS运行状态（预留）";
CM_ SG_ 2148826950 M2D_CMD1_DCDCLVoffControl_06 "DCDC低压下电控制";
CM_ SG_ 2148826950 M2D_CMD1_Reserved4_06 "预留4";
CM_ SG_ 2148826951 M2D_CMD1_CRC_07 "CRC校验";
CM_ SG_ 2148826951 M2D_CMD1_DCDCSerialNum_07 "预留  （DCDC编号）";
CM_ SG_ 2148826951 M2D_CMD1_DCDCEnable_07 "使能DCDC命令";
CM_ SG_ 2148826951 M2D_CMD1_Reserved1_07 "预留1";
CM_ SG_ 2148826951 M2D_CMD1_DCDCWrkMdSwtch_07 "DCDC工作状态切换";
CM_ SG_ 2148826951 M2D_CMD1_DCDCWrkMdSet_07 "DCDC工作模式设定";
CM_ SG_ 2148826951 M2D_CMD1_Reserved2_07 "预留2";
CM_ SG_ 2148826951 M2D_CMD1_DCDCOutputCrrntSet_07 "电池电流设定（放正充负）
电池电流=DC低压端电流+DC高压端电流";
CM_ SG_ 2148826951 M2D_CMD1_DCDCOutputVltge_Set_07 "DCDC输出电压设定";
CM_ SG_ 2148826951 M2D_CMD1_Reserved3_07 "预留3";
CM_ SG_ 2148826951 M2D_CMD1_CommunicationState_07 "MBMU与DCDC通讯状态";
CM_ SG_ 2148826951 M2D_CMD1_DCDCFaultClear_07 "DCDC故障清除指令";
CM_ SG_ 2148826951 M2D_CMD1_PCSOperationState_07 "PCS运行状态（预留）";
CM_ SG_ 2148826951 M2D_CMD1_DCDCLVoffControl_07 "DCDC低压下电控制";
CM_ SG_ 2148826951 M2D_CMD1_Reserved4_07 "预留4";
VAL_ 2165506030 RTC_CMD 0 "Reserved" 1 "Write RTC" 2 "Read RTC" ;
VAL_ 2165407726 P2S_SBMU_No 65 "SBMU1" 66 "SBMU2" 67 "SBMU3" 68 "SBMU4" 69 "SBMU5" 70 "SBMU6" 71 "SBMU7" 72 "SBMU8" 255 "All SBMU" ;
VAL_ 2165407726 RQ_Read_Detail_Data 0 "Not to read" 1 "Read real-time" 2 "Read synchronously" ;
VAL_ 2165473262 P2S_TrigCal_TankVolKB 0 "Not trigger to calibrate Tank voltage KB" 1 "Trigger to calibrate Tank voltage KB" 3 "Signal Invalid" ;
VAL_ 2165473262 P2S_Read_Cfg_Lmt 0 "Invalid" 1 "Read SBMU Configuration data" 2 "Read SBMU Limitation data" 3 "Read SBMU Configuration and Limitation data" ;
VAL_ 2165473262 P2S_CMD1_FanOnOff 0 "Reserved" 1 "Fan On" 2 "Fan Off" 3 "Signal Invalid" ;
VAL_ 2165473262 P2S_Read_CSCcfg_data 0 "do not read" 1 "read" ;
VAL_ 2165473262 P2S_CMD1_CB_CoolMode 0 "默认" 1 "开启" 2 "关闭" ;
VAL_ 2165473262 P2S_CMD1_SBMU_No 65 "SBMU1" 66 "SBMU2" 67 "SBMU3" 68 "SBMU4" 69 "SBMU5" 70 "SBMU6" 71 "SBMU7" 72 "SBMU8" 73 "SBMU9" 74 "SBMU10" 75 "SBMU11" 76 "SBMU12" 77 "SBMU13" 78 "SBMU14" 79 "SBMU15" 80 "SBMU16" 81 "SBMU17" 82 "SBMU18" 83 "SBMU19" 84 "SBMU20" 85 "SBMU21" 86 "SBMU22" 87 "SBMU23" 88 "SBMU24" 89 "SBMU25" 90 "SBMU26" 91 "SBMU27" 92 "SBMU28" 93 "SBMU29" 94 "SBMU30" 254 "ALL" ;
VAL_ 2433908718 P2S_Index_Enable 0 "Invalid" 1 "Index SBMU1" 2 "Index SBMU2" 3 "Index SBMU3" 4 "Index SBMU4" 5 "Index SBMU5" 6 "Index SBMU6" 7 "Index SBMU7" ;
VAL_ 2433122286 P2MSD_Cfg 1 "自动编码" 2 "SBMU 地址写入" 3 "DCDC 地址写入" ;
VAL_ 2433122286 P2MSD_Cfg_Addr 65 "0x41, SBMU1/DCDC1" 66 "0x42, SBMU2/DCDC2" ;
VAL_ 2433133294 P2M_Cfg5_MBMU_CMD 1 "CAN" 2 "RS485" 0 "None" ;
VAL_ 2148641518 P2M_HV_OnOff 0 "Invalid" 1 "Force to HV Off" 2 "Force to HV On" 3 "Reserved" ;
VAL_ 2148641518 P2M_Force_Heating 85 "Force to heat" 170 "Heat off" ;
VAL_ 2148641518 P2M_ForceFan_OnorOff 0 "Invalid" 1 "Force to On" 2 "Force to Off" ;
VAL_ 2148641518 P2M_ForceISO_OnorOff 0 "Force to On" 1 "Force to Off" ;
VAL_ 2148641518 PCSIsoCtrlCmd 0 "不控制" 1 "允许开启绝缘绝缘检测功能" 2 "'强制关闭绝缘检测功能" ;
VAL_ 2148707054 P2M_Read_Cfg_Lmt 0 "Invalid" 1 "Read MBMU Configuration data" 2 "Read MBMU Limitation data" 3 "Read MBMU Configuration and Limitation data" ;
VAL_ 2332164073 M2I_S1_Enable 1 "Deactive" 2 "Active" ;
VAL_ 2332164073 M2I_S1_Read_Ver_Enable 0 "invalid" 1 "Read SW-Version" 2 "Read HW-Version" 3 "Barcode" ;
VAL_ 2332164079 I2A_VoltVld 0 "invalid" 1 "Valid" ;
VAL_ 2332164079 I2A_VoltErr 0 "normal" 1 "error" ;
VAL_ 2332164079 I2A_InsResValid 0 "invalid" 1 "Valid" ;
VAL_ 2332164079 I2A_IsoResPos 0 "invalid" 1 "Valid" 2 "Init" ;
VAL_ 2483137262 P2E_Cfg5_MBMU_Add 0 "Invalid" 1 "SBMU Number" 2 "ETH Software&Hardware version" ;
VAL_ 2148826945 M2D_CMD1_DCDCEnable_01 0 "Disable" 1 "Enable" ;
VAL_ 2148826945 M2D_CMD1_DCDCWrkMdSwtch_01 0 "Standby" 1 "Normal Run" 2 "Bypass" 3 "Reserved" ;
VAL_ 2148826945 M2D_CMD1_DCDCWrkMdSet_01 0 "Constant Vlotage" 1 "Constant Current" 2 "Steady Current(not greater than)" 3 "Steady Current(not less than)" ;
VAL_ 2148826945 M2D_CMD1_DCDCOutputCrrntSet_01 1276 "Null" ;
VAL_ 2148826945 M2D_CMD1_DCDCOutputVltge_Set_01 209 "Null" ;
VAL_ 2148826945 M2D_CMD1_CommunicationState_01 0 "Normal" 1 "CAN lost" ;
VAL_ 2148826945 M2D_CMD1_DCDCFaultClear_01 0 "Not Clear" 1 "Clear" ;
VAL_ 2148826945 M2D_CMD1_PCSOperationState_01 0 "Standby" 1 "Discharge" 2 "Charge" 3 "Fault" ;
VAL_ 2148826945 M2D_CMD1_DCDCLVoffControl_01 0 "不允许低压下电" 1 "允许低压下电" ;
VAL_ 2148826946 M2D_CMD1_DCDCEnable_02 0 "Disable" 1 "Enable" ;
VAL_ 2148826946 M2D_CMD1_DCDCWrkMdSwtch_02 0 "Standby" 1 "Normal Run" 2 "Bypass" 3 "Reserved" ;
VAL_ 2148826946 M2D_CMD1_DCDCWrkMdSet_02 0 "Constant Vlotage" 1 "Constant Current" 2 "Steady Current(not greater than)" 3 "Steady Current(not less than)" ;
VAL_ 2148826946 M2D_CMD1_DCDCOutputCrrntSet_02 1276 "Null" ;
VAL_ 2148826946 M2D_CMD1_DCDCOutputVltge_Set_02 209 "Null" ;
VAL_ 2148826946 M2D_CMD1_CommunicationState_02 0 "Normal" 1 "CAN lost" ;
VAL_ 2148826946 M2D_CMD1_DCDCFaultClear_02 0 "Not Clear" 1 "Clear" ;
VAL_ 2148826946 M2D_CMD1_PCSOperationState_02 0 "Standby" 1 "Discharge" 2 "Charge" 3 "Fault" ;
VAL_ 2148826946 M2D_CMD1_DCDCLVoffControl_02 0 "不允许低压下电" 1 "允许低压下电" ;
VAL_ 2148826947 M2D_CMD1_DCDCEnable_03 0 "Disable" 1 "Enable" ;
VAL_ 2148826947 M2D_CMD1_DCDCWrkMdSwtch_03 0 "Standby" 1 "Normal Run" 2 "Bypass" 3 "Reserved" ;
VAL_ 2148826947 M2D_CMD1_DCDCWrkMdSet_03 0 "Constant Vlotage" 1 "Constant Current" 2 "Steady Current(not greater than)" 3 "Steady Current(not less than)" ;
VAL_ 2148826947 M2D_CMD1_DCDCOutputCrrntSet_03 1276 "Null" ;
VAL_ 2148826947 M2D_CMD1_DCDCOutputVltge_Set_03 209 "Null" ;
VAL_ 2148826947 M2D_CMD1_CommunicationState_03 0 "Normal" 1 "CAN lost" ;
VAL_ 2148826947 M2D_CMD1_DCDCFaultClear_03 0 "Not Clear" 1 "Clear" ;
VAL_ 2148826947 M2D_CMD1_PCSOperationState_03 0 "Standby" 1 "Discharge" 2 "Charge" 3 "Fault" ;
VAL_ 2148826947 M2D_CMD1_DCDCLVoffControl_03 0 "不允许低压下电" 1 "允许低压下电" ;
VAL_ 2148826948 M2D_CMD1_DCDCEnable_04 0 "Disable" 1 "Enable" ;
VAL_ 2148826948 M2D_CMD1_DCDCWrkMdSwtch_04 0 "Standby" 1 "Normal Run" 2 "Bypass" 3 "Reserved" ;
VAL_ 2148826948 M2D_CMD1_DCDCWrkMdSet_04 0 "Constant Vlotage" 1 "Constant Current" 2 "Steady Current(not greater than)" 3 "Steady Current(not less than)" ;
VAL_ 2148826948 M2D_CMD1_DCDCOutputCrrntSet_04 1276 "Null" ;
VAL_ 2148826948 M2D_CMD1_DCDCOutputVltge_Set_04 209 "Null" ;
VAL_ 2148826948 M2D_CMD1_CommunicationState_04 0 "Normal" 1 "CAN lost" ;
VAL_ 2148826948 M2D_CMD1_DCDCFaultClear_04 0 "Not Clear" 1 "Clear" ;
VAL_ 2148826948 M2D_CMD1_PCSOperationState_04 0 "Standby" 1 "Discharge" 2 "Charge" 3 "Fault" ;
VAL_ 2148826948 M2D_CMD1_DCDCLVoffControl_04 0 "不允许低压下电" 1 "允许低压下电" ;
VAL_ 2148826949 M2D_CMD1_DCDCEnable_05 0 "Disable" 1 "Enable" ;
VAL_ 2148826949 M2D_CMD1_DCDCWrkMdSwtch_05 0 "Standby" 1 "Normal Run" 2 "Bypass" 3 "Reserved" ;
VAL_ 2148826949 M2D_CMD1_DCDCWrkMdSet_05 0 "Constant Vlotage" 1 "Constant Current" 2 "Steady Current(not greater than)" 3 "Steady Current(not less than)" ;
VAL_ 2148826949 M2D_CMD1_DCDCOutputCrrntSet_05 1276 "Null" ;
VAL_ 2148826949 M2D_CMD1_DCDCOutputVltge_Set_05 209 "Null" ;
VAL_ 2148826949 M2D_CMD1_CommunicationState_05 0 "Normal" 1 "CAN lost" ;
VAL_ 2148826949 M2D_CMD1_DCDCFaultClear_05 0 "Not Clear" 1 "Clear" ;
VAL_ 2148826949 M2D_CMD1_PCSOperationState_05 0 "Standby" 1 "Discharge" 2 "Charge" 3 "Fault" ;
VAL_ 2148826949 M2D_CMD1_DCDCLVoffControl_05 0 "不允许低压下电" 1 "允许低压下电" ;
VAL_ 2148826950 M2D_CMD1_DCDCEnable_06 0 "Disable" 1 "Enable" ;
VAL_ 2148826950 M2D_CMD1_DCDCWrkMdSwtch_06 0 "Standby" 1 "Normal Run" 2 "Bypass" 3 "Reserved" ;
VAL_ 2148826950 M2D_CMD1_DCDCWrkMdSet_06 0 "Constant Vlotage" 1 "Constant Current" 2 "Steady Current(not greater than)" 3 "Steady Current(not less than)" ;
VAL_ 2148826950 M2D_CMD1_DCDCOutputCrrntSet_06 1276 "Null" ;
VAL_ 2148826950 M2D_CMD1_DCDCOutputVltge_Set_06 209 "Null" ;
VAL_ 2148826950 M2D_CMD1_CommunicationState_06 0 "Normal" 1 "CAN lost" ;
VAL_ 2148826950 M2D_CMD1_DCDCFaultClear_06 0 "Not Clear" 1 "Clear" ;
VAL_ 2148826950 M2D_CMD1_PCSOperationState_06 0 "Standby" 1 "Discharge" 2 "Charge" 3 "Fault" ;
VAL_ 2148826950 M2D_CMD1_DCDCLVoffControl_06 0 "不允许低压下电" 1 "允许低压下电" ;
VAL_ 2148826951 M2D_CMD1_DCDCEnable_07 0 "Disable" 1 "Enable" ;
VAL_ 2148826951 M2D_CMD1_DCDCWrkMdSwtch_07 0 "Standby" 1 "Normal Run" 2 "Bypass" 3 "Reserved" ;
VAL_ 2148826951 M2D_CMD1_DCDCWrkMdSet_07 0 "Constant Vlotage" 1 "Constant Current" 2 "Steady Current(not greater than)" 3 "Steady Current(not less than)" ;
VAL_ 2148826951 M2D_CMD1_DCDCOutputCrrntSet_07 1276 "Null" ;
VAL_ 2148826951 M2D_CMD1_DCDCOutputVltge_Set_07 209 "Null" ;
VAL_ 2148826951 M2D_CMD1_CommunicationState_07 0 "Normal" 1 "CAN lost" ;
VAL_ 2148826951 M2D_CMD1_DCDCFaultClear_07 0 "Not Clear" 1 "Clear" ;
VAL_ 2148826951 M2D_CMD1_PCSOperationState_07 0 "Standby" 1 "Discharge" 2 "Charge" 3 "Fault" ;
VAL_ 2148826951 M2D_CMD1_DCDCLVoffControl_07 0 "不允许低压下电" 1 "允许低压下电" ;
VERSION ""

NS_ :

BS_:

BU_: MBMU PC SBMU IMM ETH DCDC LEMS

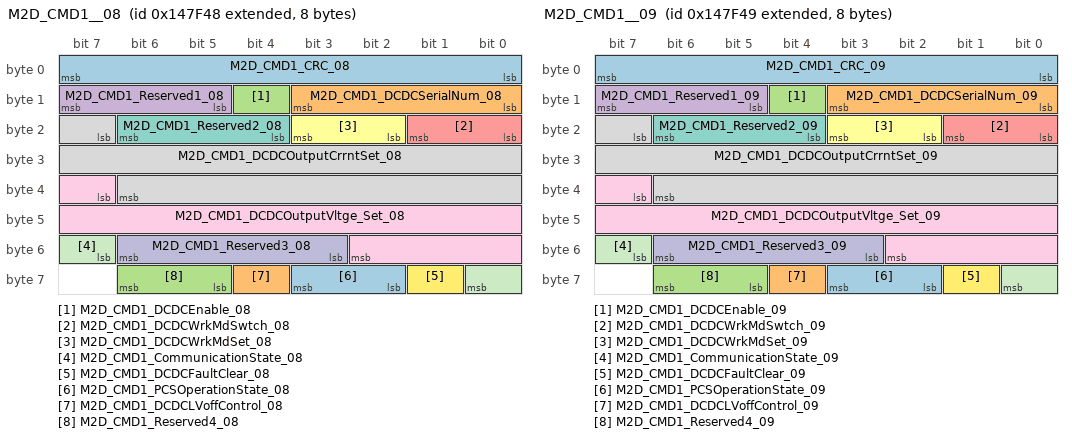
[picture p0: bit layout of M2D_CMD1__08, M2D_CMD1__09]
BO_ 2148826952 M2D_CMD1__08: 8 MBMU
 SG_ M2D_CMD1_CRC_08 : 0|8@1+ (1,0) [0|255] ""  DCDC
 SG_ M2D_CMD1_DCDCSerialNum_08 : 8|4@1+ (1,0) [0|15] ""  DCDC
 SG_ M2D_CMD1_DCDCEnable_08 : 12|1@1+ (1,0) [0|1] ""  DCDC
 SG_ M2D_CMD1_Reserved1_08 : 13|3@1+ (1,0) [0|7] ""  DCDC
 SG_ M2D_CMD1_DCDCWrkMdSwtch_08 : 16|2@1+ (1,0) [0|3] ""  DCDC
 SG_ M2D_CMD1_DCDCWrkMdSet_08 : 18|2@1+ (1,0) [0|3] ""  DCDC
 SG_ M2D_CMD1_Reserved2_08 : 20|3@1+ (1,0) [0|7] ""  DCDC
 SG_ M2D_CMD1_DCDCOutputCrrntSet_08 : 23|16@1+ (0.05,-2000) [-2000|1276.75] "A"  DCDC
 SG_ M2D_CMD1_DCDCOutputVltge_Set_08 : 39|12@1+ (0.1,-200) [-200|209.5] "V"  DCDC
 SG_ M2D_CMD1_Reserved3_08 : 51|4@1+ (1,0) [0|15] ""  DCDC
 SG_ M2D_CMD1_CommunicationState_08 : 55|2@1+ (1,0) [0|3] ""  DCDC
 SG_ M2D_CMD1_DCDCFaultClear_08 : 57|1@1+ (1,0) [0|1] ""  DCDC
 SG_ M2D_CMD1_PCSOperationState_08 : 58|2@1+ (1,0) [0|3] ""  DCDC
 SG_ M2D_CMD1_DCDCLVoffControl_08 : 60|1@1+ (1,0) [0|1] ""  DCDC
 SG_ M2D_CMD1_Reserved4_08 : 61|2@1+ (1,0) [0|3] ""  DCDC

BO_ 2148826953 M2D_CMD1__09: 8 MBMU
 SG_ M2D_CMD1_CRC_09 : 0|8@1+ (1,0) [0|255] ""  DCDC
 SG_ M2D_CMD1_DCDCSerialNum_09 : 8|4@1+ (1,0) [0|15] ""  DCDC
 SG_ M2D_CMD1_DCDCEnable_09 : 12|1@1+ (1,0) [0|1] ""  DCDC
 SG_ M2D_CMD1_Reserved1_09 : 13|3@1+ (1,0) [0|7] ""  DCDC
 SG_ M2D_CMD1_DCDCWrkMdSwtch_09 : 16|2@1+ (1,0) [0|3] ""  DCDC
 SG_ M2D_CMD1_DCDCWrkMdSet_09 : 18|2@1+ (1,0) [0|3] ""  DCDC
 SG_ M2D_CMD1_Reserved2_09 : 20|3@1+ (1,0) [0|7] ""  DCDC
 SG_ M2D_CMD1_DCDCOutputCrrntSet_09 : 23|16@1+ (0.05,-2000) [-2000|1276.75] "A"  DCDC
 SG_ M2D_CMD1_DCDCOutputVltge_Set_09 : 39|12@1+ (0.1,-200) [-200|209.5] "V"  DCDC
 SG_ M2D_CMD1_Reserved3_09 : 51|4@1+ (1,0) [0|15] ""  DCDC
 SG_ M2D_CMD1_CommunicationState_09 : 55|2@1+ (1,0) [0|3] ""  DCDC
 SG_ M2D_CMD1_DCDCFaultClear_09 : 57|1@1+ (1,0) [0|1] ""  DCDC
 SG_ M2D_CMD1_PCSOperationState_09 : 58|2@1+ (1,0) [0|3] ""  DCDC
 SG_ M2D_CMD1_DCDCLVoffControl_09 : 60|1@1+ (1,0) [0|1] ""  DCDC
 SG_ M2D_CMD1_Reserved4_09 : 61|2@1+ (1,0) [0|3] ""  DCDC

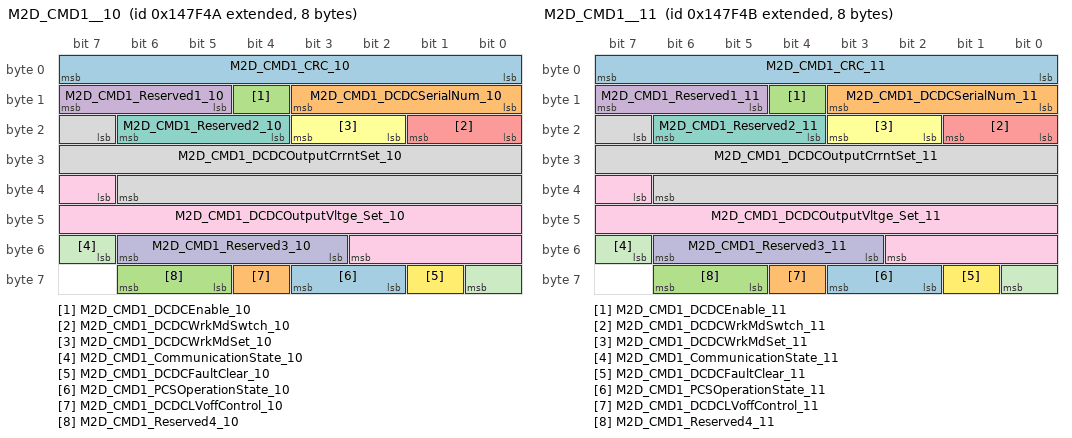
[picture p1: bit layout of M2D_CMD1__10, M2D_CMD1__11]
BO_ 2148826954 M2D_CMD1__10: 8 MBMU
 SG_ M2D_CMD1_CRC_10 : 0|8@1+ (1,0) [0|255] ""  DCDC
 SG_ M2D_CMD1_DCDCSerialNum_10 : 8|4@1+ (1,0) [0|15] ""  DCDC
 SG_ M2D_CMD1_DCDCEnable_10 : 12|1@1+ (1,0) [0|1] ""  DCDC
 SG_ M2D_CMD1_Reserved1_10 : 13|3@1+ (1,0) [0|7] ""  DCDC
 SG_ M2D_CMD1_DCDCWrkMdSwtch_10 : 16|2@1+ (1,0) [0|3] ""  DCDC
 SG_ M2D_CMD1_DCDCWrkMdSet_10 : 18|2@1+ (1,0) [0|3] ""  DCDC
 SG_ M2D_CMD1_Reserved2_10 : 20|3@1+ (1,0) [0|7] ""  DCDC
 SG_ M2D_CMD1_DCDCOutputCrrntSet_10 : 23|16@1+ (0.05,-2000) [-2000|1276.75] "A"  DCDC
 SG_ M2D_CMD1_DCDCOutputVltge_Set_10 : 39|12@1+ (0.1,-200) [-200|209.5] "V"  DCDC
 SG_ M2D_CMD1_Reserved3_10 : 51|4@1+ (1,0) [0|15] ""  DCDC
 SG_ M2D_CMD1_CommunicationState_10 : 55|2@1+ (1,0) [0|3] ""  DCDC
 SG_ M2D_CMD1_DCDCFaultClear_10 : 57|1@1+ (1,0) [0|1] ""  DCDC
 SG_ M2D_CMD1_PCSOperationState_10 : 58|2@1+ (1,0) [0|3] ""  DCDC
 SG_ M2D_CMD1_DCDCLVoffControl_10 : 60|1@1+ (1,0) [0|1] ""  DCDC
 SG_ M2D_CMD1_Reserved4_10 : 61|2@1+ (1,0) [0|3] ""  DCDC

BO_ 2148826955 M2D_CMD1__11: 8 MBMU
 SG_ M2D_CMD1_CRC_11 : 0|8@1+ (1,0) [0|255] ""  DCDC
 SG_ M2D_CMD1_DCDCSerialNum_11 : 8|4@1+ (1,0) [0|15] ""  DCDC
 SG_ M2D_CMD1_DCDCEnable_11 : 12|1@1+ (1,0) [0|1] ""  DCDC
 SG_ M2D_CMD1_Reserved1_11 : 13|3@1+ (1,0) [0|7] ""  DCDC
 SG_ M2D_CMD1_DCDCWrkMdSwtch_11 : 16|2@1+ (1,0) [0|3] ""  DCDC
 SG_ M2D_CMD1_DCDCWrkMdSet_11 : 18|2@1+ (1,0) [0|3] ""  DCDC
 SG_ M2D_CMD1_Reserved2_11 : 20|3@1+ (1,0) [0|7] ""  DCDC
 SG_ M2D_CMD1_DCDCOutputCrrntSet_11 : 23|16@1+ (0.05,-2000) [-2000|1276.75] "A"  DCDC
 SG_ M2D_CMD1_DCDCOutputVltge_Set_11 : 39|12@1+ (0.1,-200) [-200|209.5] "V"  DCDC
 SG_ M2D_CMD1_Reserved3_11 : 51|4@1+ (1,0) [0|15] ""  DCDC
 SG_ M2D_CMD1_CommunicationState_11 : 55|2@1+ (1,0) [0|3] ""  DCDC
 SG_ M2D_CMD1_DCDCFaultClear_11 : 57|1@1+ (1,0) [0|1] ""  DCDC
 SG_ M2D_CMD1_PCSOperationState_11 : 58|2@1+ (1,0) [0|3] ""  DCDC
 SG_ M2D_CMD1_DCDCLVoffControl_11 : 60|1@1+ (1,0) [0|1] ""  DCDC
 SG_ M2D_CMD1_Reserved4_11 : 61|2@1+ (1,0) [0|3] ""  DCDC

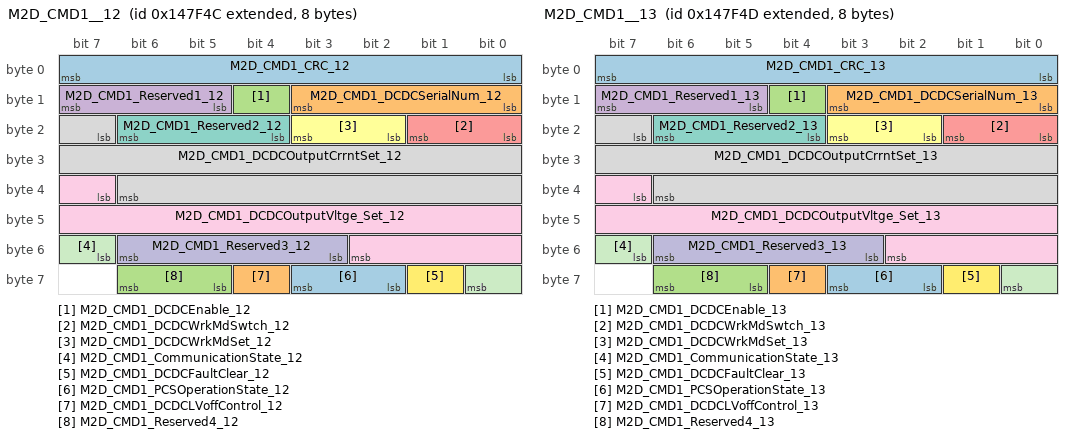
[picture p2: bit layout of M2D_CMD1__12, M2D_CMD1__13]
BO_ 2148826956 M2D_CMD1__12: 8 MBMU
 SG_ M2D_CMD1_CRC_12 : 0|8@1+ (1,0) [0|255] ""  DCDC
 SG_ M2D_CMD1_DCDCSerialNum_12 : 8|4@1+ (1,0) [0|15] ""  DCDC
 SG_ M2D_CMD1_DCDCEnable_12 : 12|1@1+ (1,0) [0|1] ""  DCDC
 SG_ M2D_CMD1_Reserved1_12 : 13|3@1+ (1,0) [0|7] ""  DCDC
 SG_ M2D_CMD1_DCDCWrkMdSwtch_12 : 16|2@1+ (1,0) [0|3] ""  DCDC
 SG_ M2D_CMD1_DCDCWrkMdSet_12 : 18|2@1+ (1,0) [0|3] ""  DCDC
 SG_ M2D_CMD1_Reserved2_12 : 20|3@1+ (1,0) [0|7] ""  DCDC
 SG_ M2D_CMD1_DCDCOutputCrrntSet_12 : 23|16@1+ (0.05,-2000) [-2000|1276.75] "A"  DCDC
 SG_ M2D_CMD1_DCDCOutputVltge_Set_12 : 39|12@1+ (0.1,-200) [-200|209.5] "V"  DCDC
 SG_ M2D_CMD1_Reserved3_12 : 51|4@1+ (1,0) [0|15] ""  DCDC
 SG_ M2D_CMD1_CommunicationState_12 : 55|2@1+ (1,0) [0|3] ""  DCDC
 SG_ M2D_CMD1_DCDCFaultClear_12 : 57|1@1+ (1,0) [0|1] ""  DCDC
 SG_ M2D_CMD1_PCSOperationState_12 : 58|2@1+ (1,0) [0|3] ""  DCDC
 SG_ M2D_CMD1_DCDCLVoffControl_12 : 60|1@1+ (1,0) [0|1] ""  DCDC
 SG_ M2D_CMD1_Reserved4_12 : 61|2@1+ (1,0) [0|3] ""  DCDC

BO_ 2148826957 M2D_CMD1__13: 8 MBMU
 SG_ M2D_CMD1_CRC_13 : 0|8@1+ (1,0) [0|255] ""  DCDC
 SG_ M2D_CMD1_DCDCSerialNum_13 : 8|4@1+ (1,0) [0|15] ""  DCDC
 SG_ M2D_CMD1_DCDCEnable_13 : 12|1@1+ (1,0) [0|1] ""  DCDC
 SG_ M2D_CMD1_Reserved1_13 : 13|3@1+ (1,0) [0|7] ""  DCDC
 SG_ M2D_CMD1_DCDCWrkMdSwtch_13 : 16|2@1+ (1,0) [0|3] ""  DCDC
 SG_ M2D_CMD1_DCDCWrkMdSet_13 : 18|2@1+ (1,0) [0|3] ""  DCDC
 SG_ M2D_CMD1_Reserved2_13 : 20|3@1+ (1,0) [0|7] ""  DCDC
 SG_ M2D_CMD1_DCDCOutputCrrntSet_13 : 23|16@1+ (0.05,-2000) [-2000|1276.75] "A"  DCDC
 SG_ M2D_CMD1_DCDCOutputVltge_Set_13 : 39|12@1+ (0.1,-200) [-200|209.5] "V"  DCDC
 SG_ M2D_CMD1_Reserved3_13 : 51|4@1+ (1,0) [0|15] ""  DCDC
 SG_ M2D_CMD1_CommunicationState_13 : 55|2@1+ (1,0) [0|3] ""  DCDC
 SG_ M2D_CMD1_DCDCFaultClear_13 : 57|1@1+ (1,0) [0|1] ""  DCDC
 SG_ M2D_CMD1_PCSOperationState_13 : 58|2@1+ (1,0) [0|3] ""  DCDC
 SG_ M2D_CMD1_DCDCLVoffControl_13 : 60|1@1+ (1,0) [0|1] ""  DCDC
 SG_ M2D_CMD1_Reserved4_13 : 61|2@1+ (1,0) [0|3] ""  DCDC

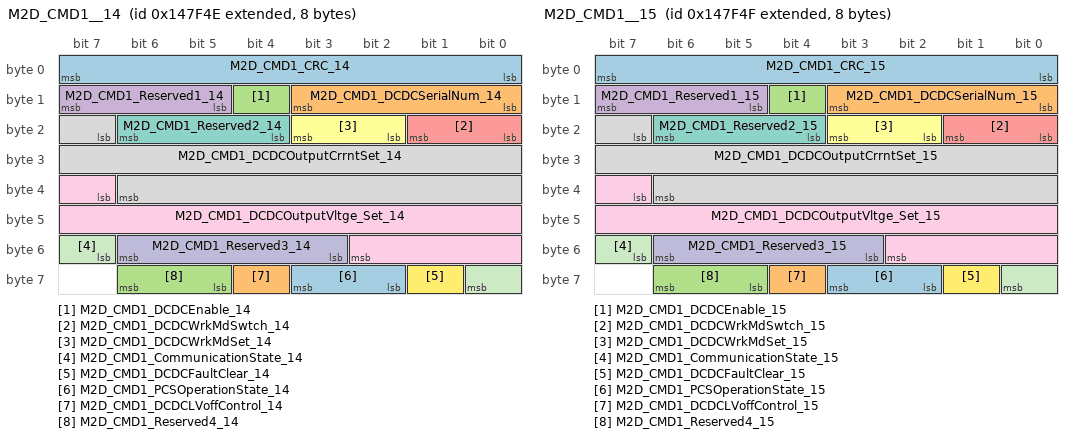
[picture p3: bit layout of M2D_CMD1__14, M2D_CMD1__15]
BO_ 2148826958 M2D_CMD1__14: 8 MBMU
 SG_ M2D_CMD1_CRC_14 : 0|8@1+ (1,0) [0|255] ""  DCDC
 SG_ M2D_CMD1_DCDCSerialNum_14 : 8|4@1+ (1,0) [0|15] ""  DCDC
 SG_ M2D_CMD1_DCDCEnable_14 : 12|1@1+ (1,0) [0|1] ""  DCDC
 SG_ M2D_CMD1_Reserved1_14 : 13|3@1+ (1,0) [0|7] ""  DCDC
 SG_ M2D_CMD1_DCDCWrkMdSwtch_14 : 16|2@1+ (1,0) [0|3] ""  DCDC
 SG_ M2D_CMD1_DCDCWrkMdSet_14 : 18|2@1+ (1,0) [0|3] ""  DCDC
 SG_ M2D_CMD1_Reserved2_14 : 20|3@1+ (1,0) [0|7] ""  DCDC
 SG_ M2D_CMD1_DCDCOutputCrrntSet_14 : 23|16@1+ (0.05,-2000) [-2000|1276.75] "A"  DCDC
 SG_ M2D_CMD1_DCDCOutputVltge_Set_14 : 39|12@1+ (0.1,-200) [-200|209.5] "V"  DCDC
 SG_ M2D_CMD1_Reserved3_14 : 51|4@1+ (1,0) [0|15] ""  DCDC
 SG_ M2D_CMD1_CommunicationState_14 : 55|2@1+ (1,0) [0|3] ""  DCDC
 SG_ M2D_CMD1_DCDCFaultClear_14 : 57|1@1+ (1,0) [0|1] ""  DCDC
 SG_ M2D_CMD1_PCSOperationState_14 : 58|2@1+ (1,0) [0|3] ""  DCDC
 SG_ M2D_CMD1_DCDCLVoffControl_14 : 60|1@1+ (1,0) [0|1] ""  DCDC
 SG_ M2D_CMD1_Reserved4_14 : 61|2@1+ (1,0) [0|3] ""  DCDC

BO_ 2148826959 M2D_CMD1__15: 8 MBMU
 SG_ M2D_CMD1_CRC_15 : 0|8@1+ (1,0) [0|255] ""  DCDC
 SG_ M2D_CMD1_DCDCSerialNum_15 : 8|4@1+ (1,0) [0|15] ""  DCDC
 SG_ M2D_CMD1_DCDCEnable_15 : 12|1@1+ (1,0) [0|1] ""  DCDC
 SG_ M2D_CMD1_Reserved1_15 : 13|3@1+ (1,0) [0|7] ""  DCDC
 SG_ M2D_CMD1_DCDCWrkMdSwtch_15 : 16|2@1+ (1,0) [0|3] ""  DCDC
 SG_ M2D_CMD1_DCDCWrkMdSet_15 : 18|2@1+ (1,0) [0|3] ""  DCDC
 SG_ M2D_CMD1_Reserved2_15 : 20|3@1+ (1,0) [0|7] ""  DCDC
 SG_ M2D_CMD1_DCDCOutputCrrntSet_15 : 23|16@1+ (0.05,-2000) [-2000|1276.75] "A"  DCDC
 SG_ M2D_CMD1_DCDCOutputVltge_Set_15 : 39|12@1+ (0.1,-200) [-200|209.5] "V"  DCDC
 SG_ M2D_CMD1_Reserved3_15 : 51|4@1+ (1,0) [0|15] ""  DCDC
 SG_ M2D_CMD1_CommunicationState_15 : 55|2@1+ (1,0) [0|3] ""  DCDC
 SG_ M2D_CMD1_DCDCFaultClear_15 : 57|1@1+ (1,0) [0|1] ""  DCDC
 SG_ M2D_CMD1_PCSOperationState_15 : 58|2@1+ (1,0) [0|3] ""  DCDC
 SG_ M2D_CMD1_DCDCLVoffControl_15 : 60|1@1+ (1,0) [0|1] ""  DCDC
 SG_ M2D_CMD1_Reserved4_15 : 61|2@1+ (1,0) [0|3] ""  DCDC

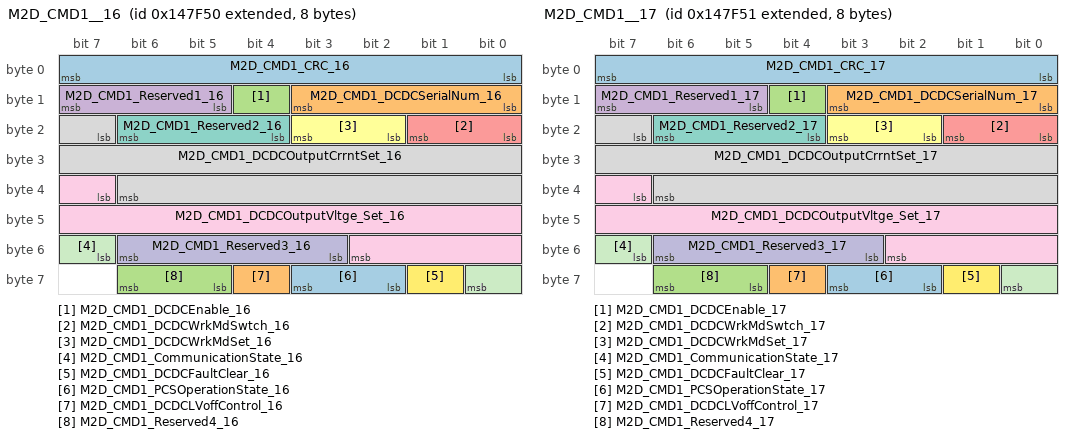
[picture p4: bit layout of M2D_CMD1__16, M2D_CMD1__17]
BO_ 2148826960 M2D_CMD1__16: 8 MBMU
 SG_ M2D_CMD1_CRC_16 : 0|8@1+ (1,0) [0|255] ""  DCDC
 SG_ M2D_CMD1_DCDCSerialNum_16 : 8|4@1+ (1,0) [0|15] ""  DCDC
 SG_ M2D_CMD1_DCDCEnable_16 : 12|1@1+ (1,0) [0|1] ""  DCDC
 SG_ M2D_CMD1_Reserved1_16 : 13|3@1+ (1,0) [0|7] ""  DCDC
 SG_ M2D_CMD1_DCDCWrkMdSwtch_16 : 16|2@1+ (1,0) [0|3] ""  DCDC
 SG_ M2D_CMD1_DCDCWrkMdSet_16 : 18|2@1+ (1,0) [0|3] ""  DCDC
 SG_ M2D_CMD1_Reserved2_16 : 20|3@1+ (1,0) [0|7] ""  DCDC
 SG_ M2D_CMD1_DCDCOutputCrrntSet_16 : 23|16@1+ (0.05,-2000) [-2000|1276.75] "A"  DCDC
 SG_ M2D_CMD1_DCDCOutputVltge_Set_16 : 39|12@1+ (0.1,-200) [-200|209.5] "V"  DCDC
 SG_ M2D_CMD1_Reserved3_16 : 51|4@1+ (1,0) [0|15] ""  DCDC
 SG_ M2D_CMD1_CommunicationState_16 : 55|2@1+ (1,0) [0|3] ""  DCDC
 SG_ M2D_CMD1_DCDCFaultClear_16 : 57|1@1+ (1,0) [0|1] ""  DCDC
 SG_ M2D_CMD1_PCSOperationState_16 : 58|2@1+ (1,0) [0|3] ""  DCDC
 SG_ M2D_CMD1_DCDCLVoffControl_16 : 60|1@1+ (1,0) [0|1] ""  DCDC
 SG_ M2D_CMD1_Reserved4_16 : 61|2@1+ (1,0) [0|3] ""  DCDC

BO_ 2148826961 M2D_CMD1__17: 8 MBMU
 SG_ M2D_CMD1_CRC_17 : 0|8@1+ (1,0) [0|255] ""  DCDC
 SG_ M2D_CMD1_DCDCSerialNum_17 : 8|4@1+ (1,0) [0|15] ""  DCDC
 SG_ M2D_CMD1_DCDCEnable_17 : 12|1@1+ (1,0) [0|1] ""  DCDC
 SG_ M2D_CMD1_Reserved1_17 : 13|3@1+ (1,0) [0|7] ""  DCDC
 SG_ M2D_CMD1_DCDCWrkMdSwtch_17 : 16|2@1+ (1,0) [0|3] ""  DCDC
 SG_ M2D_CMD1_DCDCWrkMdSet_17 : 18|2@1+ (1,0) [0|3] ""  DCDC
 SG_ M2D_CMD1_Reserved2_17 : 20|3@1+ (1,0) [0|7] ""  DCDC
 SG_ M2D_CMD1_DCDCOutputCrrntSet_17 : 23|16@1+ (0.05,-2000) [-2000|1276.75] "A"  DCDC
 SG_ M2D_CMD1_DCDCOutputVltge_Set_17 : 39|12@1+ (0.1,-200) [-200|209.5] "V"  DCDC
 SG_ M2D_CMD1_Reserved3_17 : 51|4@1+ (1,0) [0|15] ""  DCDC
 SG_ M2D_CMD1_CommunicationState_17 : 55|2@1+ (1,0) [0|3] ""  DCDC
 SG_ M2D_CMD1_DCDCFaultClear_17 : 57|1@1+ (1,0) [0|1] ""  DCDC
 SG_ M2D_CMD1_PCSOperationState_17 : 58|2@1+ (1,0) [0|3] ""  DCDC
 SG_ M2D_CMD1_DCDCLVoffControl_17 : 60|1@1+ (1,0) [0|1] ""  DCDC
 SG_ M2D_CMD1_Reserved4_17 : 61|2@1+ (1,0) [0|3] ""  DCDC

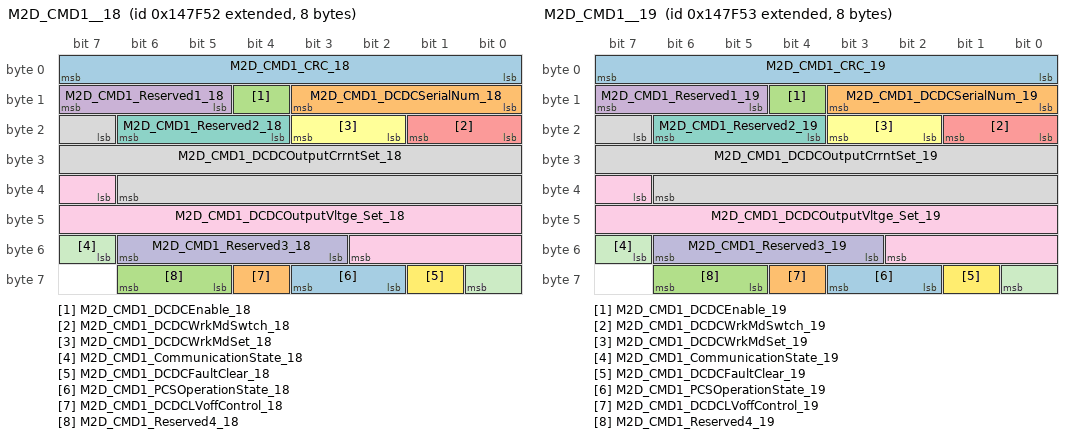
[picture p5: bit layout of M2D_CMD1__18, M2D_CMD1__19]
BO_ 2148826962 M2D_CMD1__18: 8 MBMU
 SG_ M2D_CMD1_CRC_18 : 0|8@1+ (1,0) [0|255] ""  DCDC
 SG_ M2D_CMD1_DCDCSerialNum_18 : 8|4@1+ (1,0) [0|15] ""  DCDC
 SG_ M2D_CMD1_DCDCEnable_18 : 12|1@1+ (1,0) [0|1] ""  DCDC
 SG_ M2D_CMD1_Reserved1_18 : 13|3@1+ (1,0) [0|7] ""  DCDC
 SG_ M2D_CMD1_DCDCWrkMdSwtch_18 : 16|2@1+ (1,0) [0|3] ""  DCDC
 SG_ M2D_CMD1_DCDCWrkMdSet_18 : 18|2@1+ (1,0) [0|3] ""  DCDC
 SG_ M2D_CMD1_Reserved2_18 : 20|3@1+ (1,0) [0|7] ""  DCDC
 SG_ M2D_CMD1_DCDCOutputCrrntSet_18 : 23|16@1+ (0.05,-2000) [-2000|1276.75] "A"  DCDC
 SG_ M2D_CMD1_DCDCOutputVltge_Set_18 : 39|12@1+ (0.1,-200) [-200|209.5] "V"  DCDC
 SG_ M2D_CMD1_Reserved3_18 : 51|4@1+ (1,0) [0|15] ""  DCDC
 SG_ M2D_CMD1_CommunicationState_18 : 55|2@1+ (1,0) [0|3] ""  DCDC
 SG_ M2D_CMD1_DCDCFaultClear_18 : 57|1@1+ (1,0) [0|1] ""  DCDC
 SG_ M2D_CMD1_PCSOperationState_18 : 58|2@1+ (1,0) [0|3] ""  DCDC
 SG_ M2D_CMD1_DCDCLVoffControl_18 : 60|1@1+ (1,0) [0|1] ""  DCDC
 SG_ M2D_CMD1_Reserved4_18 : 61|2@1+ (1,0) [0|3] ""  DCDC

BO_ 2148826963 M2D_CMD1__19: 8 MBMU
 SG_ M2D_CMD1_CRC_19 : 0|8@1+ (1,0) [0|255] ""  DCDC
 SG_ M2D_CMD1_DCDCSerialNum_19 : 8|4@1+ (1,0) [0|15] ""  DCDC
 SG_ M2D_CMD1_DCDCEnable_19 : 12|1@1+ (1,0) [0|1] ""  DCDC
 SG_ M2D_CMD1_Reserved1_19 : 13|3@1+ (1,0) [0|7] ""  DCDC
 SG_ M2D_CMD1_DCDCWrkMdSwtch_19 : 16|2@1+ (1,0) [0|3] ""  DCDC
 SG_ M2D_CMD1_DCDCWrkMdSet_19 : 18|2@1+ (1,0) [0|3] ""  DCDC
 SG_ M2D_CMD1_Reserved2_19 : 20|3@1+ (1,0) [0|7] ""  DCDC
 SG_ M2D_CMD1_DCDCOutputCrrntSet_19 : 23|16@1+ (0.05,-2000) [-2000|1276.75] "A"  DCDC
 SG_ M2D_CMD1_DCDCOutputVltge_Set_19 : 39|12@1+ (0.1,-200) [-200|209.5] "V"  DCDC
 SG_ M2D_CMD1_Reserved3_19 : 51|4@1+ (1,0) [0|15] ""  DCDC
 SG_ M2D_CMD1_CommunicationState_19 : 55|2@1+ (1,0) [0|3] ""  DCDC
 SG_ M2D_CMD1_DCDCFaultClear_19 : 57|1@1+ (1,0) [0|1] ""  DCDC
 SG_ M2D_CMD1_PCSOperationState_19 : 58|2@1+ (1,0) [0|3] ""  DCDC
 SG_ M2D_CMD1_DCDCLVoffControl_19 : 60|1@1+ (1,0) [0|1] ""  DCDC
 SG_ M2D_CMD1_Reserved4_19 : 61|2@1+ (1,0) [0|3] ""  DCDC

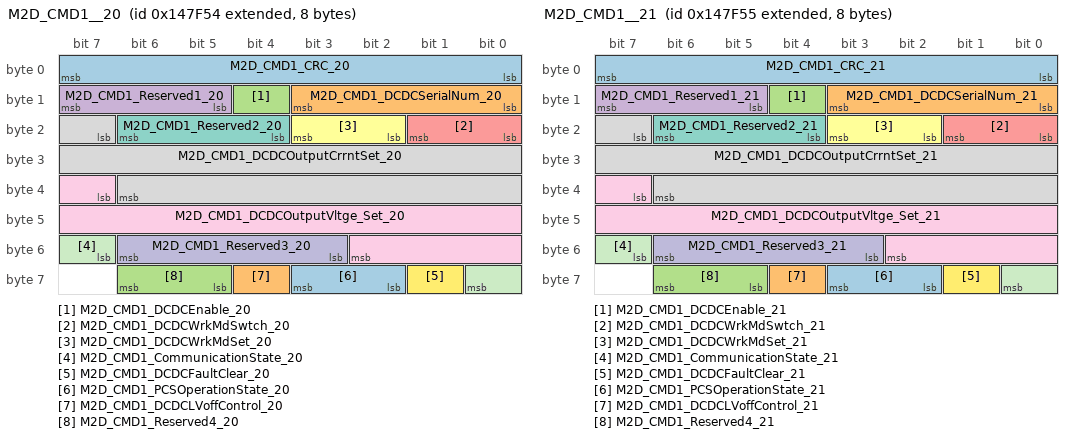
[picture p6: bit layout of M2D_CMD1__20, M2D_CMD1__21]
BO_ 2148826964 M2D_CMD1__20: 8 MBMU
 SG_ M2D_CMD1_CRC_20 : 0|8@1+ (1,0) [0|255] ""  DCDC
 SG_ M2D_CMD1_DCDCSerialNum_20 : 8|4@1+ (1,0) [0|15] ""  DCDC
 SG_ M2D_CMD1_DCDCEnable_20 : 12|1@1+ (1,0) [0|1] ""  DCDC
 SG_ M2D_CMD1_Reserved1_20 : 13|3@1+ (1,0) [0|7] ""  DCDC
 SG_ M2D_CMD1_DCDCWrkMdSwtch_20 : 16|2@1+ (1,0) [0|3] ""  DCDC
 SG_ M2D_CMD1_DCDCWrkMdSet_20 : 18|2@1+ (1,0) [0|3] ""  DCDC
 SG_ M2D_CMD1_Reserved2_20 : 20|3@1+ (1,0) [0|7] ""  DCDC
 SG_ M2D_CMD1_DCDCOutputCrrntSet_20 : 23|16@1+ (0.05,-2000) [-2000|1276.75] "A"  DCDC
 SG_ M2D_CMD1_DCDCOutputVltge_Set_20 : 39|12@1+ (0.1,-200) [-200|209.5] "V"  DCDC
 SG_ M2D_CMD1_Reserved3_20 : 51|4@1+ (1,0) [0|15] ""  DCDC
 SG_ M2D_CMD1_CommunicationState_20 : 55|2@1+ (1,0) [0|3] ""  DCDC
 SG_ M2D_CMD1_DCDCFaultClear_20 : 57|1@1+ (1,0) [0|1] ""  DCDC
 SG_ M2D_CMD1_PCSOperationState_20 : 58|2@1+ (1,0) [0|3] ""  DCDC
 SG_ M2D_CMD1_DCDCLVoffControl_20 : 60|1@1+ (1,0) [0|1] ""  DCDC
 SG_ M2D_CMD1_Reserved4_20 : 61|2@1+ (1,0) [0|3] ""  DCDC

BO_ 2148826965 M2D_CMD1__21: 8 MBMU
 SG_ M2D_CMD1_CRC_21 : 0|8@1+ (1,0) [0|255] ""  DCDC
 SG_ M2D_CMD1_DCDCSerialNum_21 : 8|4@1+ (1,0) [0|15] ""  DCDC
 SG_ M2D_CMD1_DCDCEnable_21 : 12|1@1+ (1,0) [0|1] ""  DCDC
 SG_ M2D_CMD1_Reserved1_21 : 13|3@1+ (1,0) [0|7] ""  DCDC
 SG_ M2D_CMD1_DCDCWrkMdSwtch_21 : 16|2@1+ (1,0) [0|3] ""  DCDC
 SG_ M2D_CMD1_DCDCWrkMdSet_21 : 18|2@1+ (1,0) [0|3] ""  DCDC
 SG_ M2D_CMD1_Reserved2_21 : 20|3@1+ (1,0) [0|7] ""  DCDC
 SG_ M2D_CMD1_DCDCOutputCrrntSet_21 : 23|16@1+ (0.05,-2000) [-2000|1276.75] "A"  DCDC
 SG_ M2D_CMD1_DCDCOutputVltge_Set_21 : 39|12@1+ (0.1,-200) [-200|209.5] "V"  DCDC
 SG_ M2D_CMD1_Reserved3_21 : 51|4@1+ (1,0) [0|15] ""  DCDC
 SG_ M2D_CMD1_CommunicationState_21 : 55|2@1+ (1,0) [0|3] ""  DCDC
 SG_ M2D_CMD1_DCDCFaultClear_21 : 57|1@1+ (1,0) [0|1] ""  DCDC
 SG_ M2D_CMD1_PCSOperationState_21 : 58|2@1+ (1,0) [0|3] ""  DCDC
 SG_ M2D_CMD1_DCDCLVoffControl_21 : 60|1@1+ (1,0) [0|1] ""  DCDC
 SG_ M2D_CMD1_Reserved4_21 : 61|2@1+ (1,0) [0|3] ""  DCDC

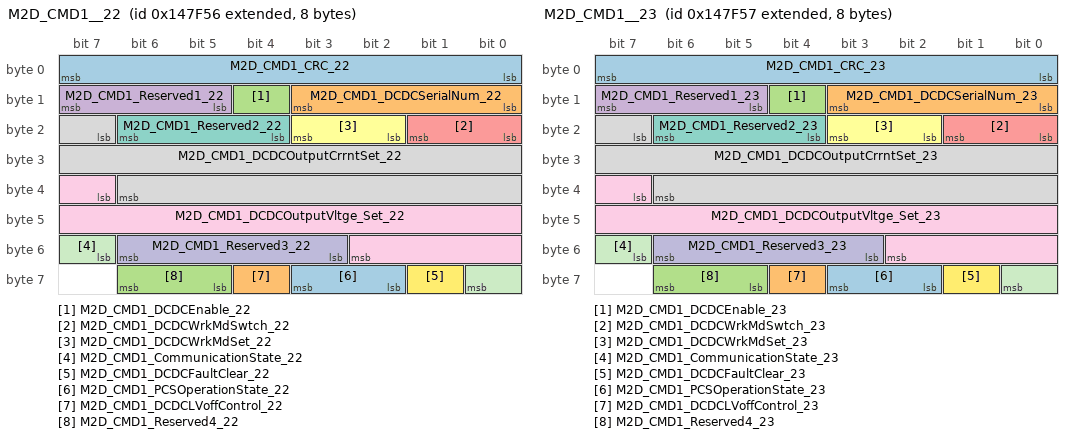
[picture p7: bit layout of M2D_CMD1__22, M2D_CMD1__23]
BO_ 2148826966 M2D_CMD1__22: 8 MBMU
 SG_ M2D_CMD1_CRC_22 : 0|8@1+ (1,0) [0|255] ""  DCDC
 SG_ M2D_CMD1_DCDCSerialNum_22 : 8|4@1+ (1,0) [0|15] ""  DCDC
 SG_ M2D_CMD1_DCDCEnable_22 : 12|1@1+ (1,0) [0|1] ""  DCDC
 SG_ M2D_CMD1_Reserved1_22 : 13|3@1+ (1,0) [0|7] ""  DCDC
 SG_ M2D_CMD1_DCDCWrkMdSwtch_22 : 16|2@1+ (1,0) [0|3] ""  DCDC
 SG_ M2D_CMD1_DCDCWrkMdSet_22 : 18|2@1+ (1,0) [0|3] ""  DCDC
 SG_ M2D_CMD1_Reserved2_22 : 20|3@1+ (1,0) [0|7] ""  DCDC
 SG_ M2D_CMD1_DCDCOutputCrrntSet_22 : 23|16@1+ (0.05,-2000) [-2000|1276.75] "A"  DCDC
 SG_ M2D_CMD1_DCDCOutputVltge_Set_22 : 39|12@1+ (0.1,-200) [-200|209.5] "V"  DCDC
 SG_ M2D_CMD1_Reserved3_22 : 51|4@1+ (1,0) [0|15] ""  DCDC
 SG_ M2D_CMD1_CommunicationState_22 : 55|2@1+ (1,0) [0|3] ""  DCDC
 SG_ M2D_CMD1_DCDCFaultClear_22 : 57|1@1+ (1,0) [0|1] ""  DCDC
 SG_ M2D_CMD1_PCSOperationState_22 : 58|2@1+ (1,0) [0|3] ""  DCDC
 SG_ M2D_CMD1_DCDCLVoffControl_22 : 60|1@1+ (1,0) [0|1] ""  DCDC
 SG_ M2D_CMD1_Reserved4_22 : 61|2@1+ (1,0) [0|3] ""  DCDC

BO_ 2148826967 M2D_CMD1__23: 8 MBMU
 SG_ M2D_CMD1_CRC_23 : 0|8@1+ (1,0) [0|255] ""  DCDC
 SG_ M2D_CMD1_DCDCSerialNum_23 : 8|4@1+ (1,0) [0|15] ""  DCDC
 SG_ M2D_CMD1_DCDCEnable_23 : 12|1@1+ (1,0) [0|1] ""  DCDC
 SG_ M2D_CMD1_Reserved1_23 : 13|3@1+ (1,0) [0|7] ""  DCDC
 SG_ M2D_CMD1_DCDCWrkMdSwtch_23 : 16|2@1+ (1,0) [0|3] ""  DCDC
 SG_ M2D_CMD1_DCDCWrkMdSet_23 : 18|2@1+ (1,0) [0|3] ""  DCDC
 SG_ M2D_CMD1_Reserved2_23 : 20|3@1+ (1,0) [0|7] ""  DCDC
 SG_ M2D_CMD1_DCDCOutputCrrntSet_23 : 23|16@1+ (0.05,-2000) [-2000|1276.75] "A"  DCDC
 SG_ M2D_CMD1_DCDCOutputVltge_Set_23 : 39|12@1+ (0.1,-200) [-200|209.5] "V"  DCDC
 SG_ M2D_CMD1_Reserved3_23 : 51|4@1+ (1,0) [0|15] ""  DCDC
 SG_ M2D_CMD1_CommunicationState_23 : 55|2@1+ (1,0) [0|3] ""  DCDC
 SG_ M2D_CMD1_DCDCFaultClear_23 : 57|1@1+ (1,0) [0|1] ""  DCDC
 SG_ M2D_CMD1_PCSOperationState_23 : 58|2@1+ (1,0) [0|3] ""  DCDC
 SG_ M2D_CMD1_DCDCLVoffControl_23 : 60|1@1+ (1,0) [0|1] ""  DCDC
 SG_ M2D_CMD1_Reserved4_23 : 61|2@1+ (1,0) [0|3] ""  DCDC

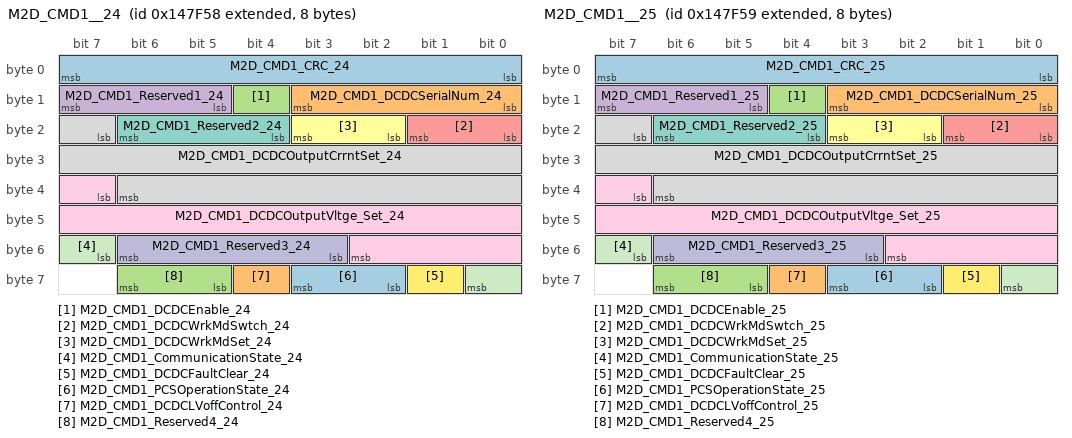
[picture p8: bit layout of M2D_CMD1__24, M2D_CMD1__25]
BO_ 2148826968 M2D_CMD1__24: 8 MBMU
 SG_ M2D_CMD1_CRC_24 : 0|8@1+ (1,0) [0|255] ""  DCDC
 SG_ M2D_CMD1_DCDCSerialNum_24 : 8|4@1+ (1,0) [0|15] ""  DCDC
 SG_ M2D_CMD1_DCDCEnable_24 : 12|1@1+ (1,0) [0|1] ""  DCDC
 SG_ M2D_CMD1_Reserved1_24 : 13|3@1+ (1,0) [0|7] ""  DCDC
 SG_ M2D_CMD1_DCDCWrkMdSwtch_24 : 16|2@1+ (1,0) [0|3] ""  DCDC
 SG_ M2D_CMD1_DCDCWrkMdSet_24 : 18|2@1+ (1,0) [0|3] ""  DCDC
 SG_ M2D_CMD1_Reserved2_24 : 20|3@1+ (1,0) [0|7] ""  DCDC
 SG_ M2D_CMD1_DCDCOutputCrrntSet_24 : 23|16@1+ (0.05,-2000) [-2000|1276.75] "A"  DCDC
 SG_ M2D_CMD1_DCDCOutputVltge_Set_24 : 39|12@1+ (0.1,-200) [-200|209.5] "V"  DCDC
 SG_ M2D_CMD1_Reserved3_24 : 51|4@1+ (1,0) [0|15] ""  DCDC
 SG_ M2D_CMD1_CommunicationState_24 : 55|2@1+ (1,0) [0|3] ""  DCDC
 SG_ M2D_CMD1_DCDCFaultClear_24 : 57|1@1+ (1,0) [0|1] ""  DCDC
 SG_ M2D_CMD1_PCSOperationState_24 : 58|2@1+ (1,0) [0|3] ""  DCDC
 SG_ M2D_CMD1_DCDCLVoffControl_24 : 60|1@1+ (1,0) [0|1] ""  DCDC
 SG_ M2D_CMD1_Reserved4_24 : 61|2@1+ (1,0) [0|3] ""  DCDC

BO_ 2148826969 M2D_CMD1__25: 8 MBMU
 SG_ M2D_CMD1_CRC_25 : 0|8@1+ (1,0) [0|255] ""  DCDC
 SG_ M2D_CMD1_DCDCSerialNum_25 : 8|4@1+ (1,0) [0|15] ""  DCDC
 SG_ M2D_CMD1_DCDCEnable_25 : 12|1@1+ (1,0) [0|1] ""  DCDC
 SG_ M2D_CMD1_Reserved1_25 : 13|3@1+ (1,0) [0|7] ""  DCDC
 SG_ M2D_CMD1_DCDCWrkMdSwtch_25 : 16|2@1+ (1,0) [0|3] ""  DCDC
 SG_ M2D_CMD1_DCDCWrkMdSet_25 : 18|2@1+ (1,0) [0|3] ""  DCDC
 SG_ M2D_CMD1_Reserved2_25 : 20|3@1+ (1,0) [0|7] ""  DCDC
 SG_ M2D_CMD1_DCDCOutputCrrntSet_25 : 23|16@1+ (0.05,-2000) [-2000|1276.75] "A"  DCDC
 SG_ M2D_CMD1_DCDCOutputVltge_Set_25 : 39|12@1+ (0.1,-200) [-200|209.5] "V"  DCDC
 SG_ M2D_CMD1_Reserved3_25 : 51|4@1+ (1,0) [0|15] ""  DCDC
 SG_ M2D_CMD1_CommunicationState_25 : 55|2@1+ (1,0) [0|3] ""  DCDC
 SG_ M2D_CMD1_DCDCFaultClear_25 : 57|1@1+ (1,0) [0|1] ""  DCDC
 SG_ M2D_CMD1_PCSOperationState_25 : 58|2@1+ (1,0) [0|3] ""  DCDC
 SG_ M2D_CMD1_DCDCLVoffControl_25 : 60|1@1+ (1,0) [0|1] ""  DCDC
 SG_ M2D_CMD1_Reserved4_25 : 61|2@1+ (1,0) [0|3] ""  DCDC

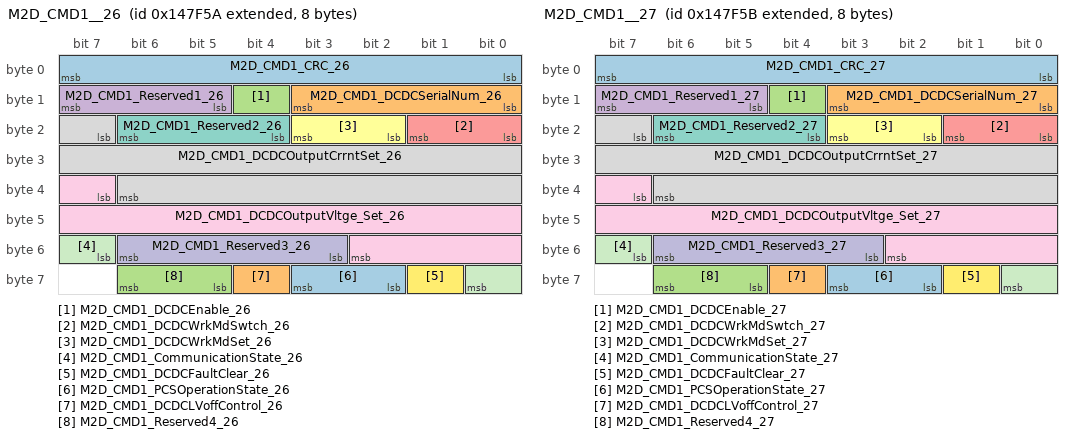
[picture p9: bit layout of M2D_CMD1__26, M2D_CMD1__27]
BO_ 2148826970 M2D_CMD1__26: 8 MBMU
 SG_ M2D_CMD1_CRC_26 : 0|8@1+ (1,0) [0|255] ""  DCDC
 SG_ M2D_CMD1_DCDCSerialNum_26 : 8|4@1+ (1,0) [0|15] ""  DCDC
 SG_ M2D_CMD1_DCDCEnable_26 : 12|1@1+ (1,0) [0|1] ""  DCDC
 SG_ M2D_CMD1_Reserved1_26 : 13|3@1+ (1,0) [0|7] ""  DCDC
 SG_ M2D_CMD1_DCDCWrkMdSwtch_26 : 16|2@1+ (1,0) [0|3] ""  DCDC
 SG_ M2D_CMD1_DCDCWrkMdSet_26 : 18|2@1+ (1,0) [0|3] ""  DCDC
 SG_ M2D_CMD1_Reserved2_26 : 20|3@1+ (1,0) [0|7] ""  DCDC
 SG_ M2D_CMD1_DCDCOutputCrrntSet_26 : 23|16@1+ (0.05,-2000) [-2000|1276.75] "A"  DCDC
 SG_ M2D_CMD1_DCDCOutputVltge_Set_26 : 39|12@1+ (0.1,-200) [-200|209.5] "V"  DCDC
 SG_ M2D_CMD1_Reserved3_26 : 51|4@1+ (1,0) [0|15] ""  DCDC
 SG_ M2D_CMD1_CommunicationState_26 : 55|2@1+ (1,0) [0|3] ""  DCDC
 SG_ M2D_CMD1_DCDCFaultClear_26 : 57|1@1+ (1,0) [0|1] ""  DCDC
 SG_ M2D_CMD1_PCSOperationState_26 : 58|2@1+ (1,0) [0|3] ""  DCDC
 SG_ M2D_CMD1_DCDCLVoffControl_26 : 60|1@1+ (1,0) [0|1] ""  DCDC
 SG_ M2D_CMD1_Reserved4_26 : 61|2@1+ (1,0) [0|3] ""  DCDC

BO_ 2148826971 M2D_CMD1__27: 8 MBMU
 SG_ M2D_CMD1_CRC_27 : 0|8@1+ (1,0) [0|255] ""  DCDC
 SG_ M2D_CMD1_DCDCSerialNum_27 : 8|4@1+ (1,0) [0|15] ""  DCDC
 SG_ M2D_CMD1_DCDCEnable_27 : 12|1@1+ (1,0) [0|1] ""  DCDC
 SG_ M2D_CMD1_Reserved1_27 : 13|3@1+ (1,0) [0|7] ""  DCDC
 SG_ M2D_CMD1_DCDCWrkMdSwtch_27 : 16|2@1+ (1,0) [0|3] ""  DCDC
 SG_ M2D_CMD1_DCDCWrkMdSet_27 : 18|2@1+ (1,0) [0|3] ""  DCDC
 SG_ M2D_CMD1_Reserved2_27 : 20|3@1+ (1,0) [0|7] ""  DCDC
 SG_ M2D_CMD1_DCDCOutputCrrntSet_27 : 23|16@1+ (0.05,-2000) [-2000|1276.75] "A"  DCDC
 SG_ M2D_CMD1_DCDCOutputVltge_Set_27 : 39|12@1+ (0.1,-200) [-200|209.5] "V"  DCDC
 SG_ M2D_CMD1_Reserved3_27 : 51|4@1+ (1,0) [0|15] ""  DCDC
 SG_ M2D_CMD1_CommunicationState_27 : 55|2@1+ (1,0) [0|3] ""  DCDC
 SG_ M2D_CMD1_DCDCFaultClear_27 : 57|1@1+ (1,0) [0|1] ""  DCDC
 SG_ M2D_CMD1_PCSOperationState_27 : 58|2@1+ (1,0) [0|3] ""  DCDC
 SG_ M2D_CMD1_DCDCLVoffControl_27 : 60|1@1+ (1,0) [0|1] ""  DCDC
 SG_ M2D_CMD1_Reserved4_27 : 61|2@1+ (1,0) [0|3] ""  DCDC

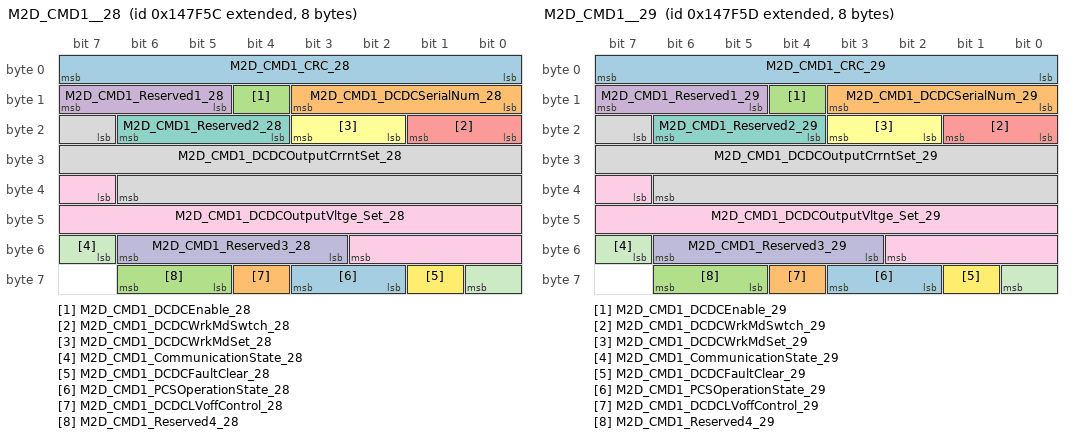
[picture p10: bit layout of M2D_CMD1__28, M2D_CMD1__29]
BO_ 2148826972 M2D_CMD1__28: 8 MBMU
 SG_ M2D_CMD1_CRC_28 : 0|8@1+ (1,0) [0|255] ""  DCDC
 SG_ M2D_CMD1_DCDCSerialNum_28 : 8|4@1+ (1,0) [0|15] ""  DCDC
 SG_ M2D_CMD1_DCDCEnable_28 : 12|1@1+ (1,0) [0|1] ""  DCDC
 SG_ M2D_CMD1_Reserved1_28 : 13|3@1+ (1,0) [0|7] ""  DCDC
 SG_ M2D_CMD1_DCDCWrkMdSwtch_28 : 16|2@1+ (1,0) [0|3] ""  DCDC
 SG_ M2D_CMD1_DCDCWrkMdSet_28 : 18|2@1+ (1,0) [0|3] ""  DCDC
 SG_ M2D_CMD1_Reserved2_28 : 20|3@1+ (1,0) [0|7] ""  DCDC
 SG_ M2D_CMD1_DCDCOutputCrrntSet_28 : 23|16@1+ (0.05,-2000) [-2000|1276.75] "A"  DCDC
 SG_ M2D_CMD1_DCDCOutputVltge_Set_28 : 39|12@1+ (0.1,-200) [-200|209.5] "V"  DCDC
 SG_ M2D_CMD1_Reserved3_28 : 51|4@1+ (1,0) [0|15] ""  DCDC
 SG_ M2D_CMD1_CommunicationState_28 : 55|2@1+ (1,0) [0|3] ""  DCDC
 SG_ M2D_CMD1_DCDCFaultClear_28 : 57|1@1+ (1,0) [0|1] ""  DCDC
 SG_ M2D_CMD1_PCSOperationState_28 : 58|2@1+ (1,0) [0|3] ""  DCDC
 SG_ M2D_CMD1_DCDCLVoffControl_28 : 60|1@1+ (1,0) [0|1] ""  DCDC
 SG_ M2D_CMD1_Reserved4_28 : 61|2@1+ (1,0) [0|3] ""  DCDC

BO_ 2148826973 M2D_CMD1__29: 8 MBMU
 SG_ M2D_CMD1_CRC_29 : 0|8@1+ (1,0) [0|255] ""  DCDC
 SG_ M2D_CMD1_DCDCSerialNum_29 : 8|4@1+ (1,0) [0|15] ""  DCDC
 SG_ M2D_CMD1_DCDCEnable_29 : 12|1@1+ (1,0) [0|1] ""  DCDC
 SG_ M2D_CMD1_Reserved1_29 : 13|3@1+ (1,0) [0|7] ""  DCDC
 SG_ M2D_CMD1_DCDCWrkMdSwtch_29 : 16|2@1+ (1,0) [0|3] ""  DCDC
 SG_ M2D_CMD1_DCDCWrkMdSet_29 : 18|2@1+ (1,0) [0|3] ""  DCDC
 SG_ M2D_CMD1_Reserved2_29 : 20|3@1+ (1,0) [0|7] ""  DCDC
 SG_ M2D_CMD1_DCDCOutputCrrntSet_29 : 23|16@1+ (0.05,-2000) [-2000|1276.75] "A"  DCDC
 SG_ M2D_CMD1_DCDCOutputVltge_Set_29 : 39|12@1+ (0.1,-200) [-200|209.5] "V"  DCDC
 SG_ M2D_CMD1_Reserved3_29 : 51|4@1+ (1,0) [0|15] ""  DCDC
 SG_ M2D_CMD1_CommunicationState_29 : 55|2@1+ (1,0) [0|3] ""  DCDC
 SG_ M2D_CMD1_DCDCFaultClear_29 : 57|1@1+ (1,0) [0|1] ""  DCDC
 SG_ M2D_CMD1_PCSOperationState_29 : 58|2@1+ (1,0) [0|3] ""  DCDC
 SG_ M2D_CMD1_DCDCLVoffControl_29 : 60|1@1+ (1,0) [0|1] ""  DCDC
 SG_ M2D_CMD1_Reserved4_29 : 61|2@1+ (1,0) [0|3] ""  DCDC

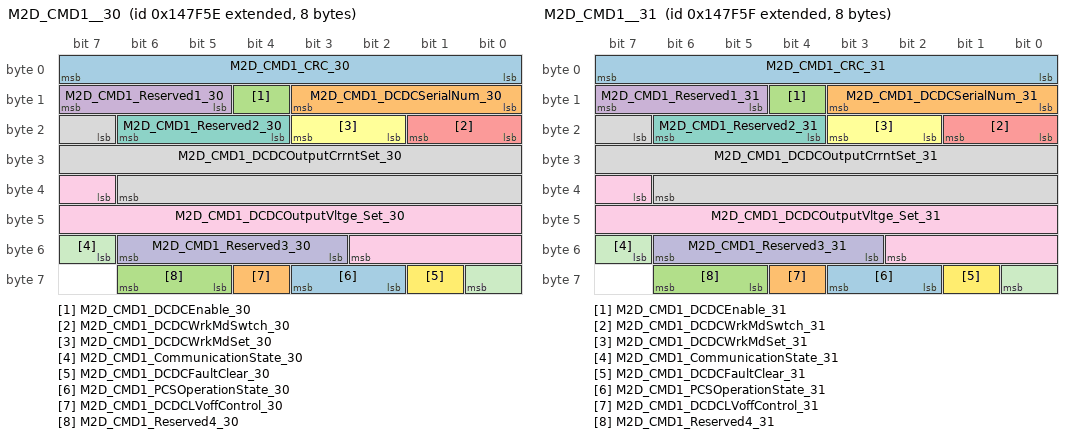
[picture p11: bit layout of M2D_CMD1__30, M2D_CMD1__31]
BO_ 2148826974 M2D_CMD1__30: 8 MBMU
 SG_ M2D_CMD1_CRC_30 : 0|8@1+ (1,0) [0|255] ""  DCDC
 SG_ M2D_CMD1_DCDCSerialNum_30 : 8|4@1+ (1,0) [0|15] ""  DCDC
 SG_ M2D_CMD1_DCDCEnable_30 : 12|1@1+ (1,0) [0|1] ""  DCDC
 SG_ M2D_CMD1_Reserved1_30 : 13|3@1+ (1,0) [0|7] ""  DCDC
 SG_ M2D_CMD1_DCDCWrkMdSwtch_30 : 16|2@1+ (1,0) [0|3] ""  DCDC
 SG_ M2D_CMD1_DCDCWrkMdSet_30 : 18|2@1+ (1,0) [0|3] ""  DCDC
 SG_ M2D_CMD1_Reserved2_30 : 20|3@1+ (1,0) [0|7] ""  DCDC
 SG_ M2D_CMD1_DCDCOutputCrrntSet_30 : 23|16@1+ (0.05,-2000) [-2000|1276.75] "A"  DCDC
 SG_ M2D_CMD1_DCDCOutputVltge_Set_30 : 39|12@1+ (0.1,-200) [-200|209.5] "V"  DCDC
 SG_ M2D_CMD1_Reserved3_30 : 51|4@1+ (1,0) [0|15] ""  DCDC
 SG_ M2D_CMD1_CommunicationState_30 : 55|2@1+ (1,0) [0|3] ""  DCDC
 SG_ M2D_CMD1_DCDCFaultClear_30 : 57|1@1+ (1,0) [0|1] ""  DCDC
 SG_ M2D_CMD1_PCSOperationState_30 : 58|2@1+ (1,0) [0|3] ""  DCDC
 SG_ M2D_CMD1_DCDCLVoffControl_30 : 60|1@1+ (1,0) [0|1] ""  DCDC
 SG_ M2D_CMD1_Reserved4_30 : 61|2@1+ (1,0) [0|3] ""  DCDC

BO_ 2148826975 M2D_CMD1__31: 8 MBMU
 SG_ M2D_CMD1_CRC_31 : 0|8@1+ (1,0) [0|255] ""  DCDC
 SG_ M2D_CMD1_DCDCSerialNum_31 : 8|4@1+ (1,0) [0|15] ""  DCDC
 SG_ M2D_CMD1_DCDCEnable_31 : 12|1@1+ (1,0) [0|1] ""  DCDC
 SG_ M2D_CMD1_Reserved1_31 : 13|3@1+ (1,0) [0|7] ""  DCDC
 SG_ M2D_CMD1_DCDCWrkMdSwtch_31 : 16|2@1+ (1,0) [0|3] ""  DCDC
 SG_ M2D_CMD1_DCDCWrkMdSet_31 : 18|2@1+ (1,0) [0|3] ""  DCDC
 SG_ M2D_CMD1_Reserved2_31 : 20|3@1+ (1,0) [0|7] ""  DCDC
 SG_ M2D_CMD1_DCDCOutputCrrntSet_31 : 23|16@1+ (0.05,-2000) [-2000|1276.75] "A"  DCDC
 SG_ M2D_CMD1_DCDCOutputVltge_Set_31 : 39|12@1+ (0.1,-200) [-200|209.5] "V"  DCDC
 SG_ M2D_CMD1_Reserved3_31 : 51|4@1+ (1,0) [0|15] ""  DCDC
 SG_ M2D_CMD1_CommunicationState_31 : 55|2@1+ (1,0) [0|3] ""  DCDC
 SG_ M2D_CMD1_DCDCFaultClear_31 : 57|1@1+ (1,0) [0|1] ""  DCDC
 SG_ M2D_CMD1_PCSOperationState_31 : 58|2@1+ (1,0) [0|3] ""  DCDC
 SG_ M2D_CMD1_DCDCLVoffControl_31 : 60|1@1+ (1,0) [0|1] ""  DCDC
 SG_ M2D_CMD1_Reserved4_31 : 61|2@1+ (1,0) [0|3] ""  DCDC

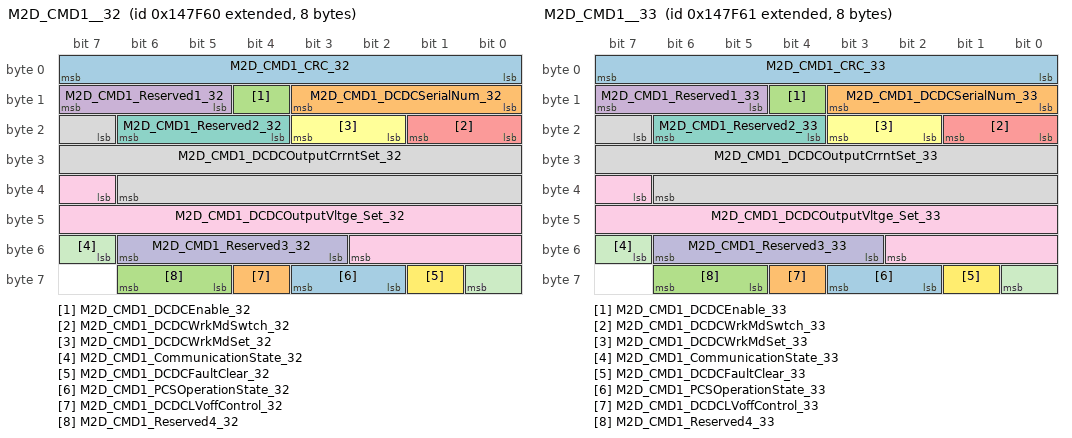
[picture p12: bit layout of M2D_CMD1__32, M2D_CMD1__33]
BO_ 2148826976 M2D_CMD1__32: 8 MBMU
 SG_ M2D_CMD1_CRC_32 : 0|8@1+ (1,0) [0|255] ""  DCDC
 SG_ M2D_CMD1_DCDCSerialNum_32 : 8|4@1+ (1,0) [0|15] ""  DCDC
 SG_ M2D_CMD1_DCDCEnable_32 : 12|1@1+ (1,0) [0|1] ""  DCDC
 SG_ M2D_CMD1_Reserved1_32 : 13|3@1+ (1,0) [0|7] ""  DCDC
 SG_ M2D_CMD1_DCDCWrkMdSwtch_32 : 16|2@1+ (1,0) [0|3] ""  DCDC
 SG_ M2D_CMD1_DCDCWrkMdSet_32 : 18|2@1+ (1,0) [0|3] ""  DCDC
 SG_ M2D_CMD1_Reserved2_32 : 20|3@1+ (1,0) [0|7] ""  DCDC
 SG_ M2D_CMD1_DCDCOutputCrrntSet_32 : 23|16@1+ (0.05,-2000) [-2000|1276.75] "A"  DCDC
 SG_ M2D_CMD1_DCDCOutputVltge_Set_32 : 39|12@1+ (0.1,-200) [-200|209.5] "V"  DCDC
 SG_ M2D_CMD1_Reserved3_32 : 51|4@1+ (1,0) [0|15] ""  DCDC
 SG_ M2D_CMD1_CommunicationState_32 : 55|2@1+ (1,0) [0|3] ""  DCDC
 SG_ M2D_CMD1_DCDCFaultClear_32 : 57|1@1+ (1,0) [0|1] ""  DCDC
 SG_ M2D_CMD1_PCSOperationState_32 : 58|2@1+ (1,0) [0|3] ""  DCDC
 SG_ M2D_CMD1_DCDCLVoffControl_32 : 60|1@1+ (1,0) [0|1] ""  DCDC
 SG_ M2D_CMD1_Reserved4_32 : 61|2@1+ (1,0) [0|3] ""  DCDC

BO_ 2148826977 M2D_CMD1__33: 8 MBMU
 SG_ M2D_CMD1_CRC_33 : 0|8@1+ (1,0) [0|255] ""  DCDC
 SG_ M2D_CMD1_DCDCSerialNum_33 : 8|4@1+ (1,0) [0|15] ""  DCDC
 SG_ M2D_CMD1_DCDCEnable_33 : 12|1@1+ (1,0) [0|1] ""  DCDC
 SG_ M2D_CMD1_Reserved1_33 : 13|3@1+ (1,0) [0|7] ""  DCDC
 SG_ M2D_CMD1_DCDCWrkMdSwtch_33 : 16|2@1+ (1,0) [0|3] ""  DCDC
 SG_ M2D_CMD1_DCDCWrkMdSet_33 : 18|2@1+ (1,0) [0|3] ""  DCDC
 SG_ M2D_CMD1_Reserved2_33 : 20|3@1+ (1,0) [0|7] ""  DCDC
 SG_ M2D_CMD1_DCDCOutputCrrntSet_33 : 23|16@1+ (0.05,-2000) [-2000|1276.75] "A"  DCDC
 SG_ M2D_CMD1_DCDCOutputVltge_Set_33 : 39|12@1+ (0.1,-200) [-200|209.5] "V"  DCDC
 SG_ M2D_CMD1_Reserved3_33 : 51|4@1+ (1,0) [0|15] ""  DCDC
 SG_ M2D_CMD1_CommunicationState_33 : 55|2@1+ (1,0) [0|3] ""  DCDC
 SG_ M2D_CMD1_DCDCFaultClear_33 : 57|1@1+ (1,0) [0|1] ""  DCDC
 SG_ M2D_CMD1_PCSOperationState_33 : 58|2@1+ (1,0) [0|3] ""  DCDC
 SG_ M2D_CMD1_DCDCLVoffControl_33 : 60|1@1+ (1,0) [0|1] ""  DCDC
 SG_ M2D_CMD1_Reserved4_33 : 61|2@1+ (1,0) [0|3] ""  DCDC

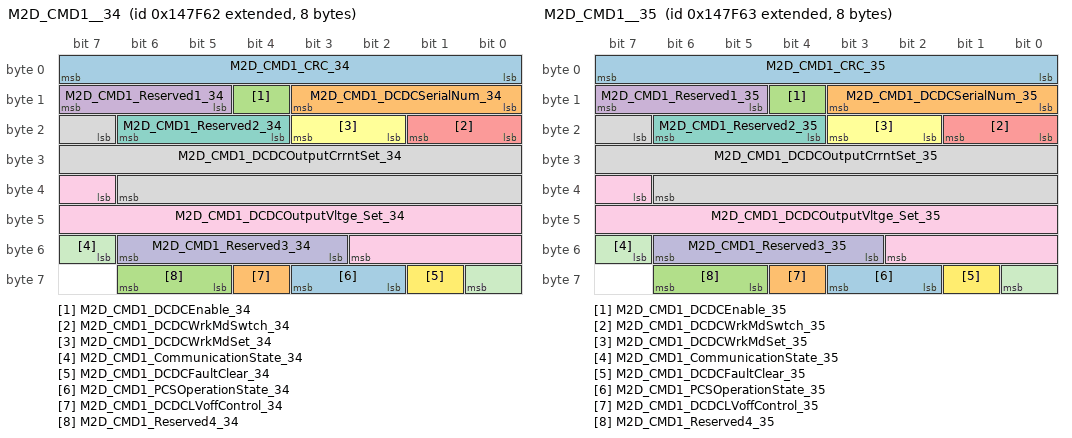
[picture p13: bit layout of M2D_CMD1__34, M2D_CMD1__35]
BO_ 2148826978 M2D_CMD1__34: 8 MBMU
 SG_ M2D_CMD1_CRC_34 : 0|8@1+ (1,0) [0|255] ""  DCDC
 SG_ M2D_CMD1_DCDCSerialNum_34 : 8|4@1+ (1,0) [0|15] ""  DCDC
 SG_ M2D_CMD1_DCDCEnable_34 : 12|1@1+ (1,0) [0|1] ""  DCDC
 SG_ M2D_CMD1_Reserved1_34 : 13|3@1+ (1,0) [0|7] ""  DCDC
 SG_ M2D_CMD1_DCDCWrkMdSwtch_34 : 16|2@1+ (1,0) [0|3] ""  DCDC
 SG_ M2D_CMD1_DCDCWrkMdSet_34 : 18|2@1+ (1,0) [0|3] ""  DCDC
 SG_ M2D_CMD1_Reserved2_34 : 20|3@1+ (1,0) [0|7] ""  DCDC
 SG_ M2D_CMD1_DCDCOutputCrrntSet_34 : 23|16@1+ (0.05,-2000) [-2000|1276.75] "A"  DCDC
 SG_ M2D_CMD1_DCDCOutputVltge_Set_34 : 39|12@1+ (0.1,-200) [-200|209.5] "V"  DCDC
 SG_ M2D_CMD1_Reserved3_34 : 51|4@1+ (1,0) [0|15] ""  DCDC
 SG_ M2D_CMD1_CommunicationState_34 : 55|2@1+ (1,0) [0|3] ""  DCDC
 SG_ M2D_CMD1_DCDCFaultClear_34 : 57|1@1+ (1,0) [0|1] ""  DCDC
 SG_ M2D_CMD1_PCSOperationState_34 : 58|2@1+ (1,0) [0|3] ""  DCDC
 SG_ M2D_CMD1_DCDCLVoffControl_34 : 60|1@1+ (1,0) [0|1] ""  DCDC
 SG_ M2D_CMD1_Reserved4_34 : 61|2@1+ (1,0) [0|3] ""  DCDC

BO_ 2148826979 M2D_CMD1__35: 8 MBMU
 SG_ M2D_CMD1_CRC_35 : 0|8@1+ (1,0) [0|255] ""  DCDC
 SG_ M2D_CMD1_DCDCSerialNum_35 : 8|4@1+ (1,0) [0|15] ""  DCDC
 SG_ M2D_CMD1_DCDCEnable_35 : 12|1@1+ (1,0) [0|1] ""  DCDC
 SG_ M2D_CMD1_Reserved1_35 : 13|3@1+ (1,0) [0|7] ""  DCDC
 SG_ M2D_CMD1_DCDCWrkMdSwtch_35 : 16|2@1+ (1,0) [0|3] ""  DCDC
 SG_ M2D_CMD1_DCDCWrkMdSet_35 : 18|2@1+ (1,0) [0|3] ""  DCDC
 SG_ M2D_CMD1_Reserved2_35 : 20|3@1+ (1,0) [0|7] ""  DCDC
 SG_ M2D_CMD1_DCDCOutputCrrntSet_35 : 23|16@1+ (0.05,-2000) [-2000|1276.75] "A"  DCDC
 SG_ M2D_CMD1_DCDCOutputVltge_Set_35 : 39|12@1+ (0.1,-200) [-200|209.5] "V"  DCDC
 SG_ M2D_CMD1_Reserved3_35 : 51|4@1+ (1,0) [0|15] ""  DCDC
 SG_ M2D_CMD1_CommunicationState_35 : 55|2@1+ (1,0) [0|3] ""  DCDC
 SG_ M2D_CMD1_DCDCFaultClear_35 : 57|1@1+ (1,0) [0|1] ""  DCDC
 SG_ M2D_CMD1_PCSOperationState_35 : 58|2@1+ (1,0) [0|3] ""  DCDC
 SG_ M2D_CMD1_DCDCLVoffControl_35 : 60|1@1+ (1,0) [0|1] ""  DCDC
 SG_ M2D_CMD1_Reserved4_35 : 61|2@1+ (1,0) [0|3] ""  DCDC

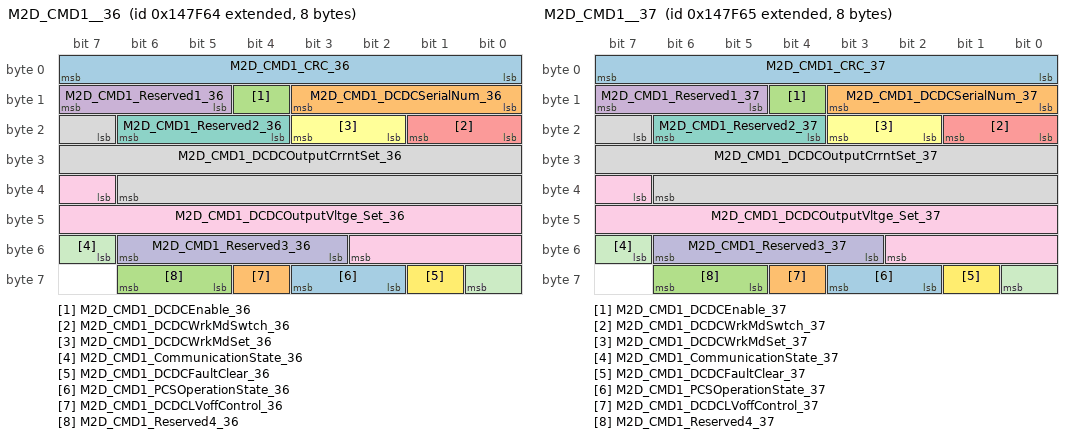
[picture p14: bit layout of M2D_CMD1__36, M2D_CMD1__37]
BO_ 2148826980 M2D_CMD1__36: 8 MBMU
 SG_ M2D_CMD1_CRC_36 : 0|8@1+ (1,0) [0|255] ""  DCDC
 SG_ M2D_CMD1_DCDCSerialNum_36 : 8|4@1+ (1,0) [0|15] ""  DCDC
 SG_ M2D_CMD1_DCDCEnable_36 : 12|1@1+ (1,0) [0|1] ""  DCDC
 SG_ M2D_CMD1_Reserved1_36 : 13|3@1+ (1,0) [0|7] ""  DCDC
 SG_ M2D_CMD1_DCDCWrkMdSwtch_36 : 16|2@1+ (1,0) [0|3] ""  DCDC
 SG_ M2D_CMD1_DCDCWrkMdSet_36 : 18|2@1+ (1,0) [0|3] ""  DCDC
 SG_ M2D_CMD1_Reserved2_36 : 20|3@1+ (1,0) [0|7] ""  DCDC
 SG_ M2D_CMD1_DCDCOutputCrrntSet_36 : 23|16@1+ (0.05,-2000) [-2000|1276.75] "A"  DCDC
 SG_ M2D_CMD1_DCDCOutputVltge_Set_36 : 39|12@1+ (0.1,-200) [-200|209.5] "V"  DCDC
 SG_ M2D_CMD1_Reserved3_36 : 51|4@1+ (1,0) [0|15] ""  DCDC
 SG_ M2D_CMD1_CommunicationState_36 : 55|2@1+ (1,0) [0|3] ""  DCDC
 SG_ M2D_CMD1_DCDCFaultClear_36 : 57|1@1+ (1,0) [0|1] ""  DCDC
 SG_ M2D_CMD1_PCSOperationState_36 : 58|2@1+ (1,0) [0|3] ""  DCDC
 SG_ M2D_CMD1_DCDCLVoffControl_36 : 60|1@1+ (1,0) [0|1] ""  DCDC
 SG_ M2D_CMD1_Reserved4_36 : 61|2@1+ (1,0) [0|3] ""  DCDC

BO_ 2148826981 M2D_CMD1__37: 8 MBMU
 SG_ M2D_CMD1_CRC_37 : 0|8@1+ (1,0) [0|255] ""  DCDC
 SG_ M2D_CMD1_DCDCSerialNum_37 : 8|4@1+ (1,0) [0|15] ""  DCDC
 SG_ M2D_CMD1_DCDCEnable_37 : 12|1@1+ (1,0) [0|1] ""  DCDC
 SG_ M2D_CMD1_Reserved1_37 : 13|3@1+ (1,0) [0|7] ""  DCDC
 SG_ M2D_CMD1_DCDCWrkMdSwtch_37 : 16|2@1+ (1,0) [0|3] ""  DCDC
 SG_ M2D_CMD1_DCDCWrkMdSet_37 : 18|2@1+ (1,0) [0|3] ""  DCDC
 SG_ M2D_CMD1_Reserved2_37 : 20|3@1+ (1,0) [0|7] ""  DCDC
 SG_ M2D_CMD1_DCDCOutputCrrntSet_37 : 23|16@1+ (0.05,-2000) [-2000|1276.75] "A"  DCDC
 SG_ M2D_CMD1_DCDCOutputVltge_Set_37 : 39|12@1+ (0.1,-200) [-200|209.5] "V"  DCDC
 SG_ M2D_CMD1_Reserved3_37 : 51|4@1+ (1,0) [0|15] ""  DCDC
 SG_ M2D_CMD1_CommunicationState_37 : 55|2@1+ (1,0) [0|3] ""  DCDC
 SG_ M2D_CMD1_DCDCFaultClear_37 : 57|1@1+ (1,0) [0|1] ""  DCDC
 SG_ M2D_CMD1_PCSOperationState_37 : 58|2@1+ (1,0) [0|3] ""  DCDC
 SG_ M2D_CMD1_DCDCLVoffControl_37 : 60|1@1+ (1,0) [0|1] ""  DCDC
 SG_ M2D_CMD1_Reserved4_37 : 61|2@1+ (1,0) [0|3] ""  DCDC

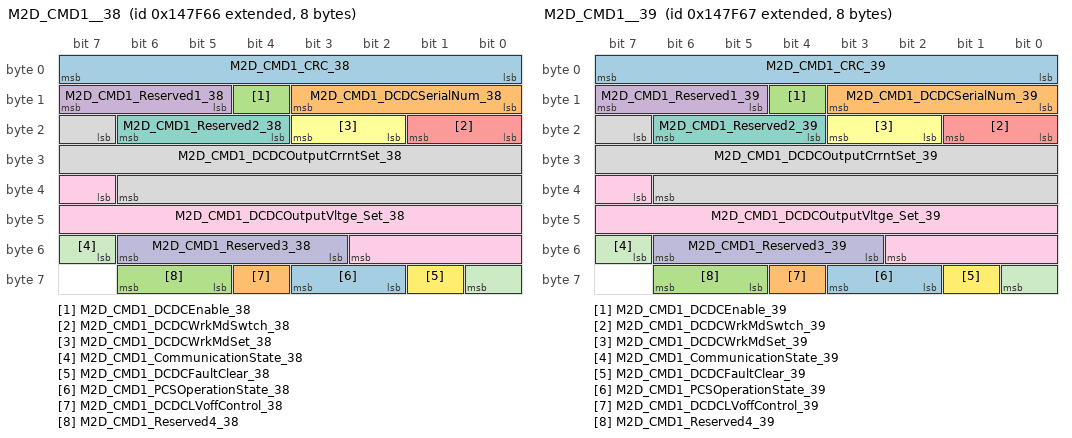
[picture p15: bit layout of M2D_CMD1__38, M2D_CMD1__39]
BO_ 2148826982 M2D_CMD1__38: 8 MBMU
 SG_ M2D_CMD1_CRC_38 : 0|8@1+ (1,0) [0|255] ""  DCDC
 SG_ M2D_CMD1_DCDCSerialNum_38 : 8|4@1+ (1,0) [0|15] ""  DCDC
 SG_ M2D_CMD1_DCDCEnable_38 : 12|1@1+ (1,0) [0|1] ""  DCDC
 SG_ M2D_CMD1_Reserved1_38 : 13|3@1+ (1,0) [0|7] ""  DCDC
 SG_ M2D_CMD1_DCDCWrkMdSwtch_38 : 16|2@1+ (1,0) [0|3] ""  DCDC
 SG_ M2D_CMD1_DCDCWrkMdSet_38 : 18|2@1+ (1,0) [0|3] ""  DCDC
 SG_ M2D_CMD1_Reserved2_38 : 20|3@1+ (1,0) [0|7] ""  DCDC
 SG_ M2D_CMD1_DCDCOutputCrrntSet_38 : 23|16@1+ (0.05,-2000) [-2000|1276.75] "A"  DCDC
 SG_ M2D_CMD1_DCDCOutputVltge_Set_38 : 39|12@1+ (0.1,-200) [-200|209.5] "V"  DCDC
 SG_ M2D_CMD1_Reserved3_38 : 51|4@1+ (1,0) [0|15] ""  DCDC
 SG_ M2D_CMD1_CommunicationState_38 : 55|2@1+ (1,0) [0|3] ""  DCDC
 SG_ M2D_CMD1_DCDCFaultClear_38 : 57|1@1+ (1,0) [0|1] ""  DCDC
 SG_ M2D_CMD1_PCSOperationState_38 : 58|2@1+ (1,0) [0|3] ""  DCDC
 SG_ M2D_CMD1_DCDCLVoffControl_38 : 60|1@1+ (1,0) [0|1] ""  DCDC
 SG_ M2D_CMD1_Reserved4_38 : 61|2@1+ (1,0) [0|3] ""  DCDC

BO_ 2148826983 M2D_CMD1__39: 8 MBMU
 SG_ M2D_CMD1_CRC_39 : 0|8@1+ (1,0) [0|255] ""  DCDC
 SG_ M2D_CMD1_DCDCSerialNum_39 : 8|4@1+ (1,0) [0|15] ""  DCDC
 SG_ M2D_CMD1_DCDCEnable_39 : 12|1@1+ (1,0) [0|1] ""  DCDC
 SG_ M2D_CMD1_Reserved1_39 : 13|3@1+ (1,0) [0|7] ""  DCDC
 SG_ M2D_CMD1_DCDCWrkMdSwtch_39 : 16|2@1+ (1,0) [0|3] ""  DCDC
 SG_ M2D_CMD1_DCDCWrkMdSet_39 : 18|2@1+ (1,0) [0|3] ""  DCDC
 SG_ M2D_CMD1_Reserved2_39 : 20|3@1+ (1,0) [0|7] ""  DCDC
 SG_ M2D_CMD1_DCDCOutputCrrntSet_39 : 23|16@1+ (0.05,-2000) [-2000|1276.75] "A"  DCDC
 SG_ M2D_CMD1_DCDCOutputVltge_Set_39 : 39|12@1+ (0.1,-200) [-200|209.5] "V"  DCDC
 SG_ M2D_CMD1_Reserved3_39 : 51|4@1+ (1,0) [0|15] ""  DCDC
 SG_ M2D_CMD1_CommunicationState_39 : 55|2@1+ (1,0) [0|3] ""  DCDC
 SG_ M2D_CMD1_DCDCFaultClear_39 : 57|1@1+ (1,0) [0|1] ""  DCDC
 SG_ M2D_CMD1_PCSOperationState_39 : 58|2@1+ (1,0) [0|3] ""  DCDC
 SG_ M2D_CMD1_DCDCLVoffControl_39 : 60|1@1+ (1,0) [0|1] ""  DCDC
 SG_ M2D_CMD1_Reserved4_39 : 61|2@1+ (1,0) [0|3] ""  DCDC

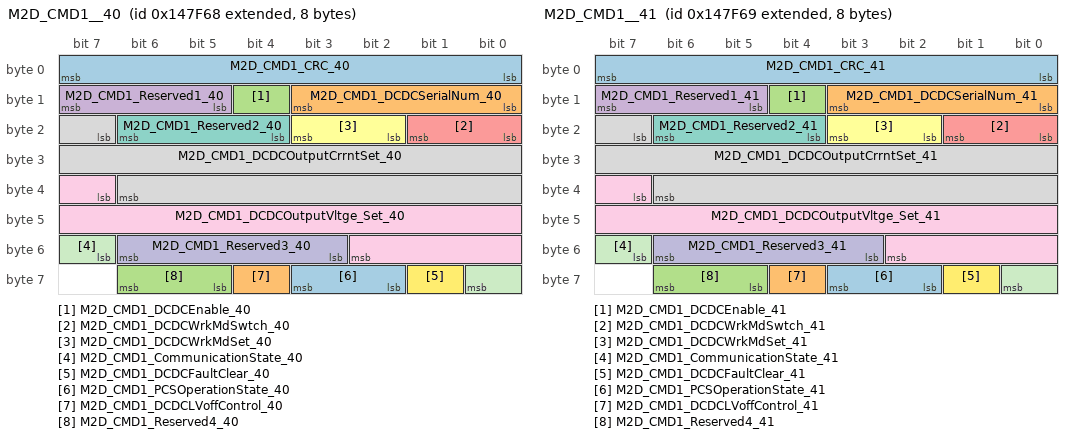
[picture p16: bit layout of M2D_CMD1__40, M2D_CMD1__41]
BO_ 2148826984 M2D_CMD1__40: 8 MBMU
 SG_ M2D_CMD1_CRC_40 : 0|8@1+ (1,0) [0|255] ""  DCDC
 SG_ M2D_CMD1_DCDCSerialNum_40 : 8|4@1+ (1,0) [0|15] ""  DCDC
 SG_ M2D_CMD1_DCDCEnable_40 : 12|1@1+ (1,0) [0|1] ""  DCDC
 SG_ M2D_CMD1_Reserved1_40 : 13|3@1+ (1,0) [0|7] ""  DCDC
 SG_ M2D_CMD1_DCDCWrkMdSwtch_40 : 16|2@1+ (1,0) [0|3] ""  DCDC
 SG_ M2D_CMD1_DCDCWrkMdSet_40 : 18|2@1+ (1,0) [0|3] ""  DCDC
 SG_ M2D_CMD1_Reserved2_40 : 20|3@1+ (1,0) [0|7] ""  DCDC
 SG_ M2D_CMD1_DCDCOutputCrrntSet_40 : 23|16@1+ (0.05,-2000) [-2000|1276.75] "A"  DCDC
 SG_ M2D_CMD1_DCDCOutputVltge_Set_40 : 39|12@1+ (0.1,-200) [-200|209.5] "V"  DCDC
 SG_ M2D_CMD1_Reserved3_40 : 51|4@1+ (1,0) [0|15] ""  DCDC
 SG_ M2D_CMD1_CommunicationState_40 : 55|2@1+ (1,0) [0|3] ""  DCDC
 SG_ M2D_CMD1_DCDCFaultClear_40 : 57|1@1+ (1,0) [0|1] ""  DCDC
 SG_ M2D_CMD1_PCSOperationState_40 : 58|2@1+ (1,0) [0|3] ""  DCDC
 SG_ M2D_CMD1_DCDCLVoffControl_40 : 60|1@1+ (1,0) [0|1] ""  DCDC
 SG_ M2D_CMD1_Reserved4_40 : 61|2@1+ (1,0) [0|3] ""  DCDC

BO_ 2148826985 M2D_CMD1__41: 8 MBMU
 SG_ M2D_CMD1_CRC_41 : 0|8@1+ (1,0) [0|255] ""  DCDC
 SG_ M2D_CMD1_DCDCSerialNum_41 : 8|4@1+ (1,0) [0|15] ""  DCDC
 SG_ M2D_CMD1_DCDCEnable_41 : 12|1@1+ (1,0) [0|1] ""  DCDC
 SG_ M2D_CMD1_Reserved1_41 : 13|3@1+ (1,0) [0|7] ""  DCDC
 SG_ M2D_CMD1_DCDCWrkMdSwtch_41 : 16|2@1+ (1,0) [0|3] ""  DCDC
 SG_ M2D_CMD1_DCDCWrkMdSet_41 : 18|2@1+ (1,0) [0|3] ""  DCDC
 SG_ M2D_CMD1_Reserved2_41 : 20|3@1+ (1,0) [0|7] ""  DCDC
 SG_ M2D_CMD1_DCDCOutputCrrntSet_41 : 23|16@1+ (0.05,-2000) [-2000|1276.75] "A"  DCDC
 SG_ M2D_CMD1_DCDCOutputVltge_Set_41 : 39|12@1+ (0.1,-200) [-200|209.5] "V"  DCDC
 SG_ M2D_CMD1_Reserved3_41 : 51|4@1+ (1,0) [0|15] ""  DCDC
 SG_ M2D_CMD1_CommunicationState_41 : 55|2@1+ (1,0) [0|3] ""  DCDC
 SG_ M2D_CMD1_DCDCFaultClear_41 : 57|1@1+ (1,0) [0|1] ""  DCDC
 SG_ M2D_CMD1_PCSOperationState_41 : 58|2@1+ (1,0) [0|3] ""  DCDC
 SG_ M2D_CMD1_DCDCLVoffControl_41 : 60|1@1+ (1,0) [0|1] ""  DCDC
 SG_ M2D_CMD1_Reserved4_41 : 61|2@1+ (1,0) [0|3] ""  DCDC

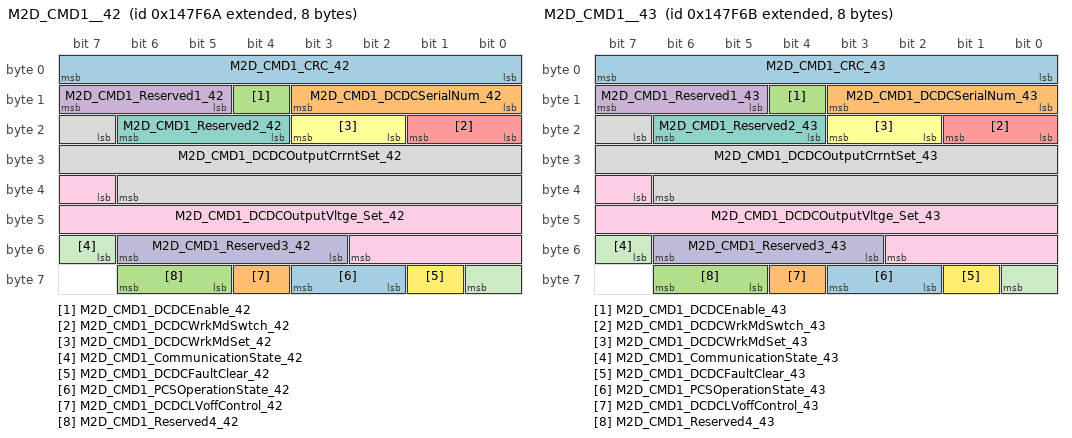
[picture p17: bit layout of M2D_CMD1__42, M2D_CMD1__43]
BO_ 2148826986 M2D_CMD1__42: 8 MBMU
 SG_ M2D_CMD1_CRC_42 : 0|8@1+ (1,0) [0|255] ""  DCDC
 SG_ M2D_CMD1_DCDCSerialNum_42 : 8|4@1+ (1,0) [0|15] ""  DCDC
 SG_ M2D_CMD1_DCDCEnable_42 : 12|1@1+ (1,0) [0|1] ""  DCDC
 SG_ M2D_CMD1_Reserved1_42 : 13|3@1+ (1,0) [0|7] ""  DCDC
 SG_ M2D_CMD1_DCDCWrkMdSwtch_42 : 16|2@1+ (1,0) [0|3] ""  DCDC
 SG_ M2D_CMD1_DCDCWrkMdSet_42 : 18|2@1+ (1,0) [0|3] ""  DCDC
 SG_ M2D_CMD1_Reserved2_42 : 20|3@1+ (1,0) [0|7] ""  DCDC
 SG_ M2D_CMD1_DCDCOutputCrrntSet_42 : 23|16@1+ (0.05,-2000) [-2000|1276.75] "A"  DCDC
 SG_ M2D_CMD1_DCDCOutputVltge_Set_42 : 39|12@1+ (0.1,-200) [-200|209.5] "V"  DCDC
 SG_ M2D_CMD1_Reserved3_42 : 51|4@1+ (1,0) [0|15] ""  DCDC
 SG_ M2D_CMD1_CommunicationState_42 : 55|2@1+ (1,0) [0|3] ""  DCDC
 SG_ M2D_CMD1_DCDCFaultClear_42 : 57|1@1+ (1,0) [0|1] ""  DCDC
 SG_ M2D_CMD1_PCSOperationState_42 : 58|2@1+ (1,0) [0|3] ""  DCDC
 SG_ M2D_CMD1_DCDCLVoffControl_42 : 60|1@1+ (1,0) [0|1] ""  DCDC
 SG_ M2D_CMD1_Reserved4_42 : 61|2@1+ (1,0) [0|3] ""  DCDC

BO_ 2148826987 M2D_CMD1__43: 8 MBMU
 SG_ M2D_CMD1_CRC_43 : 0|8@1+ (1,0) [0|255] ""  DCDC
 SG_ M2D_CMD1_DCDCSerialNum_43 : 8|4@1+ (1,0) [0|15] ""  DCDC
 SG_ M2D_CMD1_DCDCEnable_43 : 12|1@1+ (1,0) [0|1] ""  DCDC
 SG_ M2D_CMD1_Reserved1_43 : 13|3@1+ (1,0) [0|7] ""  DCDC
 SG_ M2D_CMD1_DCDCWrkMdSwtch_43 : 16|2@1+ (1,0) [0|3] ""  DCDC
 SG_ M2D_CMD1_DCDCWrkMdSet_43 : 18|2@1+ (1,0) [0|3] ""  DCDC
 SG_ M2D_CMD1_Reserved2_43 : 20|3@1+ (1,0) [0|7] ""  DCDC
 SG_ M2D_CMD1_DCDCOutputCrrntSet_43 : 23|16@1+ (0.05,-2000) [-2000|1276.75] "A"  DCDC
 SG_ M2D_CMD1_DCDCOutputVltge_Set_43 : 39|12@1+ (0.1,-200) [-200|209.5] "V"  DCDC
 SG_ M2D_CMD1_Reserved3_43 : 51|4@1+ (1,0) [0|15] ""  DCDC
 SG_ M2D_CMD1_CommunicationState_43 : 55|2@1+ (1,0) [0|3] ""  DCDC
 SG_ M2D_CMD1_DCDCFaultClear_43 : 57|1@1+ (1,0) [0|1] ""  DCDC
 SG_ M2D_CMD1_PCSOperationState_43 : 58|2@1+ (1,0) [0|3] ""  DCDC
 SG_ M2D_CMD1_DCDCLVoffControl_43 : 60|1@1+ (1,0) [0|1] ""  DCDC
 SG_ M2D_CMD1_Reserved4_43 : 61|2@1+ (1,0) [0|3] ""  DCDC

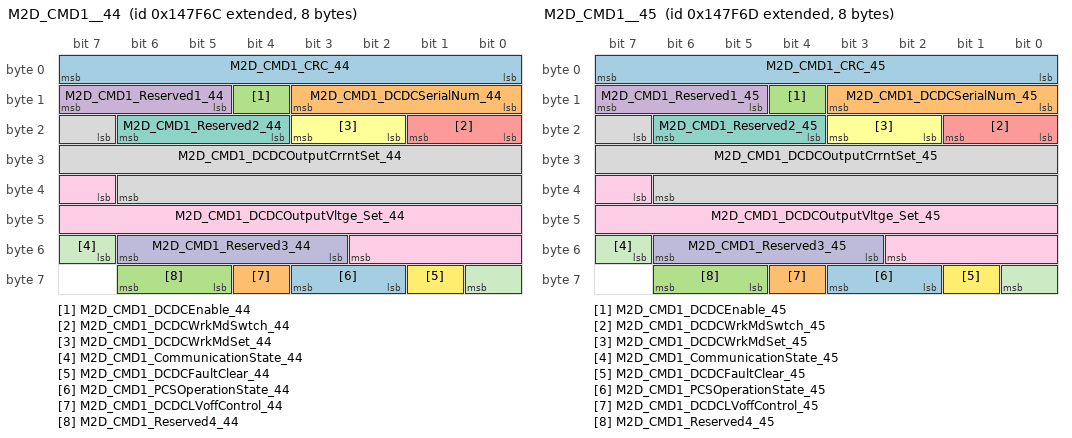
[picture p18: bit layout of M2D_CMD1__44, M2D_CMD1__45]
BO_ 2148826988 M2D_CMD1__44: 8 MBMU
 SG_ M2D_CMD1_CRC_44 : 0|8@1+ (1,0) [0|255] ""  DCDC
 SG_ M2D_CMD1_DCDCSerialNum_44 : 8|4@1+ (1,0) [0|15] ""  DCDC
 SG_ M2D_CMD1_DCDCEnable_44 : 12|1@1+ (1,0) [0|1] ""  DCDC
 SG_ M2D_CMD1_Reserved1_44 : 13|3@1+ (1,0) [0|7] ""  DCDC
 SG_ M2D_CMD1_DCDCWrkMdSwtch_44 : 16|2@1+ (1,0) [0|3] ""  DCDC
 SG_ M2D_CMD1_DCDCWrkMdSet_44 : 18|2@1+ (1,0) [0|3] ""  DCDC
 SG_ M2D_CMD1_Reserved2_44 : 20|3@1+ (1,0) [0|7] ""  DCDC
 SG_ M2D_CMD1_DCDCOutputCrrntSet_44 : 23|16@1+ (0.05,-2000) [-2000|1276.75] "A"  DCDC
 SG_ M2D_CMD1_DCDCOutputVltge_Set_44 : 39|12@1+ (0.1,-200) [-200|209.5] "V"  DCDC
 SG_ M2D_CMD1_Reserved3_44 : 51|4@1+ (1,0) [0|15] ""  DCDC
 SG_ M2D_CMD1_CommunicationState_44 : 55|2@1+ (1,0) [0|3] ""  DCDC
 SG_ M2D_CMD1_DCDCFaultClear_44 : 57|1@1+ (1,0) [0|1] ""  DCDC
 SG_ M2D_CMD1_PCSOperationState_44 : 58|2@1+ (1,0) [0|3] ""  DCDC
 SG_ M2D_CMD1_DCDCLVoffControl_44 : 60|1@1+ (1,0) [0|1] ""  DCDC
 SG_ M2D_CMD1_Reserved4_44 : 61|2@1+ (1,0) [0|3] ""  DCDC

BO_ 2148826989 M2D_CMD1__45: 8 MBMU
 SG_ M2D_CMD1_CRC_45 : 0|8@1+ (1,0) [0|255] ""  DCDC
 SG_ M2D_CMD1_DCDCSerialNum_45 : 8|4@1+ (1,0) [0|15] ""  DCDC
 SG_ M2D_CMD1_DCDCEnable_45 : 12|1@1+ (1,0) [0|1] ""  DCDC
 SG_ M2D_CMD1_Reserved1_45 : 13|3@1+ (1,0) [0|7] ""  DCDC
 SG_ M2D_CMD1_DCDCWrkMdSwtch_45 : 16|2@1+ (1,0) [0|3] ""  DCDC
 SG_ M2D_CMD1_DCDCWrkMdSet_45 : 18|2@1+ (1,0) [0|3] ""  DCDC
 SG_ M2D_CMD1_Reserved2_45 : 20|3@1+ (1,0) [0|7] ""  DCDC
 SG_ M2D_CMD1_DCDCOutputCrrntSet_45 : 23|16@1+ (0.05,-2000) [-2000|1276.75] "A"  DCDC
 SG_ M2D_CMD1_DCDCOutputVltge_Set_45 : 39|12@1+ (0.1,-200) [-200|209.5] "V"  DCDC
 SG_ M2D_CMD1_Reserved3_45 : 51|4@1+ (1,0) [0|15] ""  DCDC
 SG_ M2D_CMD1_CommunicationState_45 : 55|2@1+ (1,0) [0|3] ""  DCDC
 SG_ M2D_CMD1_DCDCFaultClear_45 : 57|1@1+ (1,0) [0|1] ""  DCDC
 SG_ M2D_CMD1_PCSOperationState_45 : 58|2@1+ (1,0) [0|3] ""  DCDC
 SG_ M2D_CMD1_DCDCLVoffControl_45 : 60|1@1+ (1,0) [0|1] ""  DCDC
 SG_ M2D_CMD1_Reserved4_45 : 61|2@1+ (1,0) [0|3] ""  DCDC

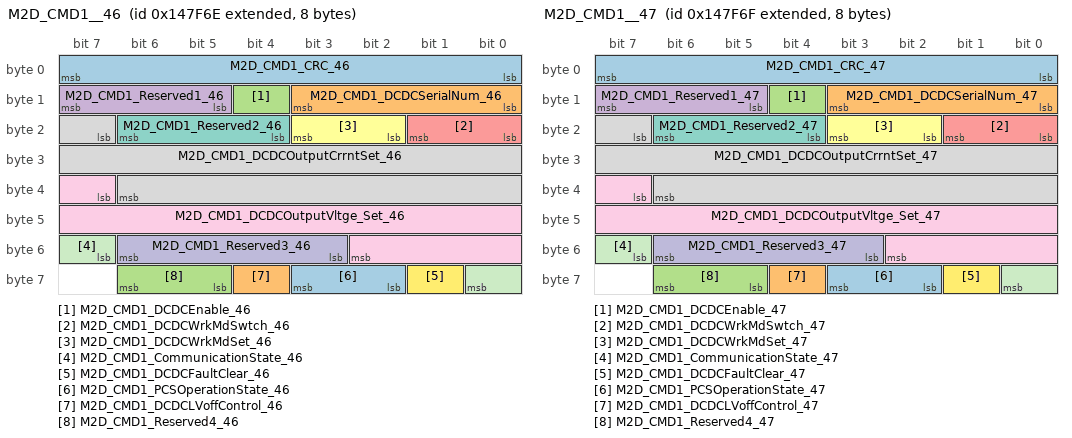
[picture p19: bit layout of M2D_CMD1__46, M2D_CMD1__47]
BO_ 2148826990 M2D_CMD1__46: 8 MBMU
 SG_ M2D_CMD1_CRC_46 : 0|8@1+ (1,0) [0|255] ""  DCDC
 SG_ M2D_CMD1_DCDCSerialNum_46 : 8|4@1+ (1,0) [0|15] ""  DCDC
 SG_ M2D_CMD1_DCDCEnable_46 : 12|1@1+ (1,0) [0|1] ""  DCDC
 SG_ M2D_CMD1_Reserved1_46 : 13|3@1+ (1,0) [0|7] ""  DCDC
 SG_ M2D_CMD1_DCDCWrkMdSwtch_46 : 16|2@1+ (1,0) [0|3] ""  DCDC
 SG_ M2D_CMD1_DCDCWrkMdSet_46 : 18|2@1+ (1,0) [0|3] ""  DCDC
 SG_ M2D_CMD1_Reserved2_46 : 20|3@1+ (1,0) [0|7] ""  DCDC
 SG_ M2D_CMD1_DCDCOutputCrrntSet_46 : 23|16@1+ (0.05,-2000) [-2000|1276.75] "A"  DCDC
 SG_ M2D_CMD1_DCDCOutputVltge_Set_46 : 39|12@1+ (0.1,-200) [-200|209.5] "V"  DCDC
 SG_ M2D_CMD1_Reserved3_46 : 51|4@1+ (1,0) [0|15] ""  DCDC
 SG_ M2D_CMD1_CommunicationState_46 : 55|2@1+ (1,0) [0|3] ""  DCDC
 SG_ M2D_CMD1_DCDCFaultClear_46 : 57|1@1+ (1,0) [0|1] ""  DCDC
 SG_ M2D_CMD1_PCSOperationState_46 : 58|2@1+ (1,0) [0|3] ""  DCDC
 SG_ M2D_CMD1_DCDCLVoffControl_46 : 60|1@1+ (1,0) [0|1] ""  DCDC
 SG_ M2D_CMD1_Reserved4_46 : 61|2@1+ (1,0) [0|3] ""  DCDC

BO_ 2148826991 M2D_CMD1__47: 8 MBMU
 SG_ M2D_CMD1_CRC_47 : 0|8@1+ (1,0) [0|255] ""  DCDC
 SG_ M2D_CMD1_DCDCSerialNum_47 : 8|4@1+ (1,0) [0|15] ""  DCDC
 SG_ M2D_CMD1_DCDCEnable_47 : 12|1@1+ (1,0) [0|1] ""  DCDC
 SG_ M2D_CMD1_Reserved1_47 : 13|3@1+ (1,0) [0|7] ""  DCDC
 SG_ M2D_CMD1_DCDCWrkMdSwtch_47 : 16|2@1+ (1,0) [0|3] ""  DCDC
 SG_ M2D_CMD1_DCDCWrkMdSet_47 : 18|2@1+ (1,0) [0|3] ""  DCDC
 SG_ M2D_CMD1_Reserved2_47 : 20|3@1+ (1,0) [0|7] ""  DCDC
 SG_ M2D_CMD1_DCDCOutputCrrntSet_47 : 23|16@1+ (0.05,-2000) [-2000|1276.75] "A"  DCDC
 SG_ M2D_CMD1_DCDCOutputVltge_Set_47 : 39|12@1+ (0.1,-200) [-200|209.5] "V"  DCDC
 SG_ M2D_CMD1_Reserved3_47 : 51|4@1+ (1,0) [0|15] ""  DCDC
 SG_ M2D_CMD1_CommunicationState_47 : 55|2@1+ (1,0) [0|3] ""  DCDC
 SG_ M2D_CMD1_DCDCFaultClear_47 : 57|1@1+ (1,0) [0|1] ""  DCDC
 SG_ M2D_CMD1_PCSOperationState_47 : 58|2@1+ (1,0) [0|3] ""  DCDC
 SG_ M2D_CMD1_DCDCLVoffControl_47 : 60|1@1+ (1,0) [0|1] ""  DCDC
 SG_ M2D_CMD1_Reserved4_47 : 61|2@1+ (1,0) [0|3] ""  DCDC

BO_ 2148826992 M2D_CMD1__48: 8 MBMU
 SG_ M2D_CMD1_CRC_48 : 0|8@1+ (1,0) [0|255] ""  DCDC
 SG_ M2D_CMD1_DCDCSerialNum_48 : 8|4@1+ (1,0) [0|15] ""  DCDC
 SG_ M2D_CMD1_DCDCEnable_48 : 12|1@1+ (1,0) [0|1] ""  DCDC
 SG_ M2D_CMD1_Reserved1_48 : 13|3@1+ (1,0) [0|7] ""  DCDC
 SG_ M2D_CMD1_DCDCWrkMdSwtch_48 : 16|2@1+ (1,0) [0|3] ""  DCDC
 SG_ M2D_CMD1_DCDCWrkMdSet_48 : 18|2@1+ (1,0) [0|3] ""  DCDC
 SG_ M2D_CMD1_Reserved2_48 : 20|3@1+ (1,0) [0|7] ""  DCDC
 SG_ M2D_CMD1_DCDCOutputCrrntSet_48 : 23|16@1+ (0.05,-2000) [-2000|1276.75] "A"  DCDC
 SG_ M2D_CMD1_DCDCOutputVltge_Set_48 : 39|12@1+ (0.1,-200) [-200|209.5] "V"  DCDC
 SG_ M2D_CMD1_Reserved3_48 : 51|4@1+ (1,0) [0|15] ""  DCDC
 SG_ M2D_CMD1_CommunicationState_48 : 55|2@1+ (1,0) [0|3] ""  DCDC
 SG_ M2D_CMD1_DCDCFaultClear_48 : 57|1@1+ (1,0) [0|1] ""  DCDC
 SG_ M2D_CMD1_PCSOperationState_48 : 58|2@1+ (1,0) [0|3] ""  DCDC
 SG_ M2D_CMD1_DCDCLVoffControl_48 : 60|1@1+ (1,0) [0|1] ""  DCDC
 SG_ M2D_CMD1_Reserved4_48 : 61|2@1+ (1,0) [0|3] ""  DCDC

BO_ 2148826993 M2D_CMD1__49: 8 MBMU
 SG_ M2D_CMD1_CRC_49 : 0|8@1+ (1,0) [0|255] ""  DCDC
 SG_ M2D_CMD1_DCDCSerialNum_49 : 8|4@1+ (1,0) [0|15] ""  DCDC
 SG_ M2D_CMD1_DCDCEnable_49 : 12|1@1+ (1,0) [0|1] ""  DCDC
 SG_ M2D_CMD1_Reserved1_49 : 13|3@1+ (1,0) [0|7] ""  DCDC
 SG_ M2D_CMD1_DCDCWrkMdSwtch_49 : 16|2@1+ (1,0) [0|3] ""  DCDC
 SG_ M2D_CMD1_DCDCWrkMdSet_49 : 18|2@1+ (1,0) [0|3] ""  DCDC
 SG_ M2D_CMD1_Reserved2_49 : 20|3@1+ (1,0) [0|7] ""  DCDC
 SG_ M2D_CMD1_DCDCOutputCrrntSet_49 : 23|16@1+ (0.05,-2000) [-2000|1276.75] "A"  DCDC
 SG_ M2D_CMD1_DCDCOutputVltge_Set_49 : 39|12@1+ (0.1,-200) [-200|209.5] "V"  DCDC
 SG_ M2D_CMD1_Reserved3_49 : 51|4@1+ (1,0) [0|15] ""  DCDC
 SG_ M2D_CMD1_CommunicationState_49 : 55|2@1+ (1,0) [0|3] ""  DCDC
 SG_ M2D_CMD1_DCDCFaultClear_49 : 57|1@1+ (1,0) [0|1] ""  DCDC
 SG_ M2D_CMD1_PCSOperationState_49 : 58|2@1+ (1,0) [0|3] ""  DCDC
 SG_ M2D_CMD1_DCDCLVoffControl_49 : 60|1@1+ (1,0) [0|1] ""  DCDC
 SG_ M2D_CMD1_Reserved4_49 : 61|2@1+ (1,0) [0|3] ""  DCDC

BO_ 2148826994 M2D_CMD1__50: 8 MBMU
 SG_ M2D_CMD1_CRC_50 : 0|8@1+ (1,0) [0|255] ""  DCDC
 SG_ M2D_CMD1_DCDCSerialNum_50 : 8|4@1+ (1,0) [0|15] ""  DCDC
 SG_ M2D_CMD1_DCDCEnable_50 : 12|1@1+ (1,0) [0|1] ""  DCDC
 SG_ M2D_CMD1_Reserved1_50 : 13|3@1+ (1,0) [0|7] ""  DCDC
 SG_ M2D_CMD1_DCDCWrkMdSwtch_50 : 16|2@1+ (1,0) [0|3] ""  DCDC
 SG_ M2D_CMD1_DCDCWrkMdSet_50 : 18|2@1+ (1,0) [0|3] ""  DCDC
 SG_ M2D_CMD1_Reserved2_50 : 20|3@1+ (1,0) [0|7] ""  DCDC
 SG_ M2D_CMD1_DCDCOutputCrrntSet_50 : 23|16@1+ (0.05,-2000) [-2000|1276.75] "A"  DCDC
 SG_ M2D_CMD1_DCDCOutputVltge_Set_50 : 39|12@1+ (0.1,-200) [-200|209.5] "V"  DCDC
 SG_ M2D_CMD1_Reserved3_50 : 51|4@1+ (1,0) [0|15] ""  DCDC
 SG_ M2D_CMD1_CommunicationState_50 : 55|2@1+ (1,0) [0|3] ""  DCDC
 SG_ M2D_CMD1_DCDCFaultClear_50 : 57|1@1+ (1,0) [0|1] ""  DCDC
 SG_ M2D_CMD1_PCSOperationState_50 : 58|2@1+ (1,0) [0|3] ""  DCDC
 SG_ M2D_CMD1_DCDCLVoffControl_50 : 60|1@1+ (1,0) [0|1] ""  DCDC
 SG_ M2D_CMD1_Reserved4_50 : 61|2@1+ (1,0) [0|3] ""  DCDC

BO_ 2148826995 M2D_CMD1__51: 8 MBMU
 SG_ M2D_CMD1_CRC_51 : 0|8@1+ (1,0) [0|255] ""  DCDC
 SG_ M2D_CMD1_DCDCSerialNum_51 : 8|4@1+ (1,0) [0|15] ""  DCDC
 SG_ M2D_CMD1_DCDCEnable_51 : 12|1@1+ (1,0) [0|1] ""  DCDC
 SG_ M2D_CMD1_Reserved1_51 : 13|3@1+ (1,0) [0|7] ""  DCDC
 SG_ M2D_CMD1_DCDCWrkMdSwtch_51 : 16|2@1+ (1,0) [0|3] ""  DCDC
 SG_ M2D_CMD1_DCDCWrkMdSet_51 : 18|2@1+ (1,0) [0|3] ""  DCDC
 SG_ M2D_CMD1_Reserved2_51 : 20|3@1+ (1,0) [0|7] ""  DCDC
 SG_ M2D_CMD1_DCDCOutputCrrntSet_51 : 23|16@1+ (0.05,-2000) [-2000|1276.75] "A"  DCDC
 SG_ M2D_CMD1_DCDCOutputVltge_Set_51 : 39|12@1+ (0.1,-200) [-200|209.5] "V"  DCDC
 SG_ M2D_CMD1_Reserved3_51 : 51|4@1+ (1,0) [0|15] ""  DCDC
 SG_ M2D_CMD1_CommunicationState_51 : 55|2@1+ (1,0) [0|3] ""  DCDC
 SG_ M2D_CMD1_DCDCFaultClear_51 : 57|1@1+ (1,0) [0|1] ""  DCDC
 SG_ M2D_CMD1_PCSOperationState_51 : 58|2@1+ (1,0) [0|3] ""  DCDC
 SG_ M2D_CMD1_DCDCLVoffControl_51 : 60|1@1+ (1,0) [0|1] ""  DCDC
 SG_ M2D_CMD1_Reserved4_51 : 61|2@1+ (1,0) [0|3] ""  DCDC

BO_ 2148826996 M2D_CMD1__52: 8 MBMU
 SG_ M2D_CMD1_CRC_52 : 0|8@1+ (1,0) [0|255] ""  DCDC
 SG_ M2D_CMD1_DCDCSerialNum_52 : 8|4@1+ (1,0) [0|15] ""  DCDC
 SG_ M2D_CMD1_DCDCEnable_52 : 12|1@1+ (1,0) [0|1] ""  DCDC
 SG_ M2D_CMD1_Reserved1_52 : 13|3@1+ (1,0) [0|7] ""  DCDC
 SG_ M2D_CMD1_DCDCWrkMdSwtch_52 : 16|2@1+ (1,0) [0|3] ""  DCDC
 SG_ M2D_CMD1_DCDCWrkMdSet_52 : 18|2@1+ (1,0) [0|3] ""  DCDC
 SG_ M2D_CMD1_Reserved2_52 : 20|3@1+ (1,0) [0|7] ""  DCDC
 SG_ M2D_CMD1_DCDCOutputCrrntSet_52 : 23|16@1+ (0.05,-2000) [-2000|1276.75] "A"  DCDC
 SG_ M2D_CMD1_DCDCOutputVltge_Set_52 : 39|12@1+ (0.1,-200) [-200|209.5] "V"  DCDC
 SG_ M2D_CMD1_Reserved3_52 : 51|4@1+ (1,0) [0|15] ""  DCDC
 SG_ M2D_CMD1_CommunicationState_52 : 55|2@1+ (1,0) [0|3] ""  DCDC
 SG_ M2D_CMD1_DCDCFaultClear_52 : 57|1@1+ (1,0) [0|1] ""  DCDC
 SG_ M2D_CMD1_PCSOperationState_52 : 58|2@1+ (1,0) [0|3] ""  DCDC
 SG_ M2D_CMD1_DCDCLVoffControl_52 : 60|1@1+ (1,0) [0|1] ""  DCDC
 SG_ M2D_CMD1_Reserved4_52 : 61|2@1+ (1,0) [0|3] ""  DCDC

BO_ 2148826997 M2D_CMD1__53: 8 MBMU
 SG_ M2D_CMD1_CRC_53 : 0|8@1+ (1,0) [0|255] ""  DCDC
 SG_ M2D_CMD1_DCDCSerialNum_53 : 8|4@1+ (1,0) [0|15] ""  DCDC
 SG_ M2D_CMD1_DCDCEnable_53 : 12|1@1+ (1,0) [0|1] ""  DCDC
 SG_ M2D_CMD1_Reserved1_53 : 13|3@1+ (1,0) [0|7] ""  DCDC
 SG_ M2D_CMD1_DCDCWrkMdSwtch_53 : 16|2@1+ (1,0) [0|3] ""  DCDC
 SG_ M2D_CMD1_DCDCWrkMdSet_53 : 18|2@1+ (1,0) [0|3] ""  DCDC
 SG_ M2D_CMD1_Reserved2_53 : 20|3@1+ (1,0) [0|7] ""  DCDC
 SG_ M2D_CMD1_DCDCOutputCrrntSet_53 : 23|16@1+ (0.05,-2000) [-2000|1276.75] "A"  DCDC
 SG_ M2D_CMD1_DCDCOutputVltge_Set_53 : 39|12@1+ (0.1,-200) [-200|209.5] "V"  DCDC
 SG_ M2D_CMD1_Reserved3_53 : 51|4@1+ (1,0) [0|15] ""  DCDC
 SG_ M2D_CMD1_CommunicationState_53 : 55|2@1+ (1,0) [0|3] ""  DCDC
 SG_ M2D_CMD1_DCDCFaultClear_53 : 57|1@1+ (1,0) [0|1] ""  DCDC
 SG_ M2D_CMD1_PCSOperationState_53 : 58|2@1+ (1,0) [0|3] ""  DCDC
 SG_ M2D_CMD1_DCDCLVoffControl_53 : 60|1@1+ (1,0) [0|1] ""  DCDC
 SG_ M2D_CMD1_Reserved4_53 : 61|2@1+ (1,0) [0|3] ""  DCDC

BO_ 2148826998 M2D_CMD1__54: 8 MBMU
 SG_ M2D_CMD1_CRC_54 : 0|8@1+ (1,0) [0|255] ""  DCDC
 SG_ M2D_CMD1_DCDCSerialNum_54 : 8|4@1+ (1,0) [0|15] ""  DCDC
 SG_ M2D_CMD1_DCDCEnable_54 : 12|1@1+ (1,0) [0|1] ""  DCDC
 SG_ M2D_CMD1_Reserved1_54 : 13|3@1+ (1,0) [0|7] ""  DCDC
 SG_ M2D_CMD1_DCDCWrkMdSwtch_54 : 16|2@1+ (1,0) [0|3] ""  DCDC
 SG_ M2D_CMD1_DCDCWrkMdSet_54 : 18|2@1+ (1,0) [0|3] ""  DCDC
 SG_ M2D_CMD1_Reserved2_54 : 20|3@1+ (1,0) [0|7] ""  DCDC
 SG_ M2D_CMD1_DCDCOutputCrrntSet_54 : 23|16@1+ (0.05,-2000) [-2000|1276.75] "A"  DCDC
 SG_ M2D_CMD1_DCDCOutputVltge_Set_54 : 39|12@1+ (0.1,-200) [-200|209.5] "V"  DCDC
 SG_ M2D_CMD1_Reserved3_54 : 51|4@1+ (1,0) [0|15] ""  DCDC
 SG_ M2D_CMD1_CommunicationState_54 : 55|2@1+ (1,0) [0|3] ""  DCDC
 SG_ M2D_CMD1_DCDCFaultClear_54 : 57|1@1+ (1,0) [0|1] ""  DCDC
 SG_ M2D_CMD1_PCSOperationState_54 : 58|2@1+ (1,0) [0|3] ""  DCDC
 SG_ M2D_CMD1_DCDCLVoffControl_54 : 60|1@1+ (1,0) [0|1] ""  DCDC
 SG_ M2D_CMD1_Reserved4_54 : 61|2@1+ (1,0) [0|3] ""  DCDC

BO_ 2148826999 M2D_CMD1__55: 8 MBMU
 SG_ M2D_CMD1_CRC_55 : 0|8@1+ (1,0) [0|255] ""  DCDC
 SG_ M2D_CMD1_DCDCSerialNum_55 : 8|4@1+ (1,0) [0|15] ""  DCDC
 SG_ M2D_CMD1_DCDCEnable_55 : 12|1@1+ (1,0) [0|1] ""  DCDC
 SG_ M2D_CMD1_Reserved1_55 : 13|3@1+ (1,0) [0|7] ""  DCDC
 SG_ M2D_CMD1_DCDCWrkMdSwtch_55 : 16|2@1+ (1,0) [0|3] ""  DCDC
 SG_ M2D_CMD1_DCDCWrkMdSet_55 : 18|2@1+ (1,0) [0|3] ""  DCDC
 SG_ M2D_CMD1_Reserved2_55 : 20|3@1+ (1,0) [0|7] ""  DCDC
 SG_ M2D_CMD1_DCDCOutputCrrntSet_55 : 23|16@1+ (0.05,-2000) [-2000|1276.75] "A"  DCDC
 SG_ M2D_CMD1_DCDCOutputVltge_Set_55 : 39|12@1+ (0.1,-200) [-200|209.5] "V"  DCDC
 SG_ M2D_CMD1_Reserved3_55 : 51|4@1+ (1,0) [0|15] ""  DCDC
 SG_ M2D_CMD1_CommunicationState_55 : 55|2@1+ (1,0) [0|3] ""  DCDC
 SG_ M2D_CMD1_DCDCFaultClear_55 : 57|1@1+ (1,0) [0|1] ""  DCDC
 SG_ M2D_CMD1_PCSOperationState_55 : 58|2@1+ (1,0) [0|3] ""  DCDC
 SG_ M2D_CMD1_DCDCLVoffControl_55 : 60|1@1+ (1,0) [0|1] ""  DCDC
 SG_ M2D_CMD1_Reserved4_55 : 61|2@1+ (1,0) [0|3] ""  DCDC

BO_ 2148827000 M2D_CMD1__56: 8 MBMU
 SG_ M2D_CMD1_CRC_56 : 0|8@1+ (1,0) [0|255] ""  DCDC
 SG_ M2D_CMD1_DCDCSerialNum_56 : 8|4@1+ (1,0) [0|15] ""  DCDC
 SG_ M2D_CMD1_DCDCEnable_56 : 12|1@1+ (1,0) [0|1] ""  DCDC
 SG_ M2D_CMD1_Reserved1_56 : 13|3@1+ (1,0) [0|7] ""  DCDC
 SG_ M2D_CMD1_DCDCWrkMdSwtch_56 : 16|2@1+ (1,0) [0|3] ""  DCDC
 SG_ M2D_CMD1_DCDCWrkMdSet_56 : 18|2@1+ (1,0) [0|3] ""  DCDC
 SG_ M2D_CMD1_Reserved2_56 : 20|3@1+ (1,0) [0|7] ""  DCDC
 SG_ M2D_CMD1_DCDCOutputCrrntSet_56 : 23|16@1+ (0.05,-2000) [-2000|1276.75] "A"  DCDC
 SG_ M2D_CMD1_DCDCOutputVltge_Set_56 : 39|12@1+ (0.1,-200) [-200|209.5] "V"  DCDC
 SG_ M2D_CMD1_Reserved3_56 : 51|4@1+ (1,0) [0|15] ""  DCDC
 SG_ M2D_CMD1_CommunicationState_56 : 55|2@1+ (1,0) [0|3] ""  DCDC
 SG_ M2D_CMD1_DCDCFaultClear_56 : 57|1@1+ (1,0) [0|1] ""  DCDC
 SG_ M2D_CMD1_PCSOperationState_56 : 58|2@1+ (1,0) [0|3] ""  DCDC
 SG_ M2D_CMD1_DCDCLVoffControl_56 : 60|1@1+ (1,0) [0|1] ""  DCDC
 SG_ M2D_CMD1_Reserved4_56 : 61|2@1+ (1,0) [0|3] ""  DCDC

BO_ 2148827001 M2D_CMD1__57: 8 MBMU
 SG_ M2D_CMD1_CRC_57 : 0|8@1+ (1,0) [0|255] ""  DCDC
 SG_ M2D_CMD1_DCDCSerialNum_57 : 8|4@1+ (1,0) [0|15] ""  DCDC
 SG_ M2D_CMD1_DCDCEnable_57 : 12|1@1+ (1,0) [0|1] ""  DCDC
 SG_ M2D_CMD1_Reserved1_57 : 13|3@1+ (1,0) [0|7] ""  DCDC
 SG_ M2D_CMD1_DCDCWrkMdSwtch_57 : 16|2@1+ (1,0) [0|3] ""  DCDC
 SG_ M2D_CMD1_DCDCWrkMdSet_57 : 18|2@1+ (1,0) [0|3] ""  DCDC
 SG_ M2D_CMD1_Reserved2_57 : 20|3@1+ (1,0) [0|7] ""  DCDC
 SG_ M2D_CMD1_DCDCOutputCrrntSet_57 : 23|16@1+ (0.05,-2000) [-2000|1276.75] "A"  DCDC
 SG_ M2D_CMD1_DCDCOutputVltge_Set_57 : 39|12@1+ (0.1,-200) [-200|209.5] "V"  DCDC
 SG_ M2D_CMD1_Reserved3_57 : 51|4@1+ (1,0) [0|15] ""  DCDC
 SG_ M2D_CMD1_CommunicationState_57 : 55|2@1+ (1,0) [0|3] ""  DCDC
 SG_ M2D_CMD1_DCDCFaultClear_57 : 57|1@1+ (1,0) [0|1] ""  DCDC
 SG_ M2D_CMD1_PCSOperationState_57 : 58|2@1+ (1,0) [0|3] ""  DCDC
 SG_ M2D_CMD1_DCDCLVoffControl_57 : 60|1@1+ (1,0) [0|1] ""  DCDC
 SG_ M2D_CMD1_Reserved4_57 : 61|2@1+ (1,0) [0|3] ""  DCDC

BO_ 2148827002 M2D_CMD1__58: 8 MBMU
 SG_ M2D_CMD1_CRC_58 : 0|8@1+ (1,0) [0|255] ""  DCDC
 SG_ M2D_CMD1_DCDCSerialNum_58 : 8|4@1+ (1,0) [0|15] ""  DCDC
 SG_ M2D_CMD1_DCDCEnable_58 : 12|1@1+ (1,0) [0|1] ""  DCDC
 SG_ M2D_CMD1_Reserved1_58 : 13|3@1+ (1,0) [0|7] ""  DCDC
 SG_ M2D_CMD1_DCDCWrkMdSwtch_58 : 16|2@1+ (1,0) [0|3] ""  DCDC
 SG_ M2D_CMD1_DCDCWrkMdSet_58 : 18|2@1+ (1,0) [0|3] ""  DCDC
 SG_ M2D_CMD1_Reserved2_58 : 20|3@1+ (1,0) [0|7] ""  DCDC
 SG_ M2D_CMD1_DCDCOutputCrrntSet_58 : 23|16@1+ (0.05,-2000) [-2000|1276.75] "A"  DCDC
 SG_ M2D_CMD1_DCDCOutputVltge_Set_58 : 39|12@1+ (0.1,-200) [-200|209.5] "V"  DCDC
 SG_ M2D_CMD1_Reserved3_58 : 51|4@1+ (1,0) [0|15] ""  DCDC
 SG_ M2D_CMD1_CommunicationState_58 : 55|2@1+ (1,0) [0|3] ""  DCDC
 SG_ M2D_CMD1_DCDCFaultClear_58 : 57|1@1+ (1,0) [0|1] ""  DCDC
 SG_ M2D_CMD1_PCSOperationState_58 : 58|2@1+ (1,0) [0|3] ""  DCDC
 SG_ M2D_CMD1_DCDCLVoffControl_58 : 60|1@1+ (1,0) [0|1] ""  DCDC
 SG_ M2D_CMD1_Reserved4_58 : 61|2@1+ (1,0) [0|3] ""  DCDC

BO_ 2148827003 M2D_CMD1__59: 8 MBMU
 SG_ M2D_CMD1_CRC_59 : 0|8@1+ (1,0) [0|255] ""  DCDC
 SG_ M2D_CMD1_DCDCSerialNum_59 : 8|4@1+ (1,0) [0|15] ""  DCDC
 SG_ M2D_CMD1_DCDCEnable_59 : 12|1@1+ (1,0) [0|1] ""  DCDC
 SG_ M2D_CMD1_Reserved1_59 : 13|3@1+ (1,0) [0|7] ""  DCDC
 SG_ M2D_CMD1_DCDCWrkMdSwtch_59 : 16|2@1+ (1,0) [0|3] ""  DCDC
 SG_ M2D_CMD1_DCDCWrkMdSet_59 : 18|2@1+ (1,0) [0|3] ""  DCDC
 SG_ M2D_CMD1_Reserved2_59 : 20|3@1+ (1,0) [0|7] ""  DCDC
 SG_ M2D_CMD1_DCDCOutputCrrntSet_59 : 23|16@1+ (0.05,-2000) [-2000|1276.75] "A"  DCDC
 SG_ M2D_CMD1_DCDCOutputVltge_Set_59 : 39|12@1+ (0.1,-200) [-200|209.5] "V"  DCDC
 SG_ M2D_CMD1_Reserved3_59 : 51|4@1+ (1,0) [0|15] ""  DCDC
 SG_ M2D_CMD1_CommunicationState_59 : 55|2@1+ (1,0) [0|3] ""  DCDC
 SG_ M2D_CMD1_DCDCFaultClear_59 : 57|1@1+ (1,0) [0|1] ""  DCDC
 SG_ M2D_CMD1_PCSOperationState_59 : 58|2@1+ (1,0) [0|3] ""  DCDC
 SG_ M2D_CMD1_DCDCLVoffControl_59 : 60|1@1+ (1,0) [0|1] ""  DCDC
 SG_ M2D_CMD1_Reserved4_59 : 61|2@1+ (1,0) [0|3] ""  DCDC

BO_ 2148827004 M2D_CMD1__60: 8 MBMU
 SG_ M2D_CMD1_CRC_60 : 0|8@1+ (1,0) [0|255] ""  DCDC
 SG_ M2D_CMD1_DCDCSerialNum_60 : 8|4@1+ (1,0) [0|15] ""  DCDC
 SG_ M2D_CMD1_DCDCEnable_60 : 12|1@1+ (1,0) [0|1] ""  DCDC
 SG_ M2D_CMD1_Reserved1_60 : 13|3@1+ (1,0) [0|7] ""  DCDC
 SG_ M2D_CMD1_DCDCWrkMdSwtch_60 : 16|2@1+ (1,0) [0|3] ""  DCDC
 SG_ M2D_CMD1_DCDCWrkMdSet_60 : 18|2@1+ (1,0) [0|3] ""  DCDC
 SG_ M2D_CMD1_Reserved2_60 : 20|3@1+ (1,0) [0|7] ""  DCDC
 SG_ M2D_CMD1_DCDCOutputCrrntSet_60 : 23|16@1+ (0.05,-2000) [-2000|1276.75] "A"  DCDC
 SG_ M2D_CMD1_DCDCOutputVltge_Set_60 : 39|12@1+ (0.1,-200) [-200|209.5] "V"  DCDC
 SG_ M2D_CMD1_Reserved3_60 : 51|4@1+ (1,0) [0|15] ""  DCDC
 SG_ M2D_CMD1_CommunicationState_60 : 55|2@1+ (1,0) [0|3] ""  DCDC
 SG_ M2D_CMD1_DCDCFaultClear_60 : 57|1@1+ (1,0) [0|1] ""  DCDC
 SG_ M2D_CMD1_PCSOperationState_60 : 58|2@1+ (1,0) [0|3] ""  DCDC
 SG_ M2D_CMD1_DCDCLVoffControl_60 : 60|1@1+ (1,0) [0|1] ""  DCDC
 SG_ M2D_CMD1_Reserved4_60 : 61|2@1+ (1,0) [0|3] ""  DCDC

BO_ 2148827005 M2D_CMD1__61: 8 MBMU
 SG_ M2D_CMD1_CRC_61 : 0|8@1+ (1,0) [0|255] ""  DCDC
 SG_ M2D_CMD1_DCDCSerialNum_61 : 8|4@1+ (1,0) [0|15] ""  DCDC
 SG_ M2D_CMD1_DCDCEnable_61 : 12|1@1+ (1,0) [0|1] ""  DCDC
 SG_ M2D_CMD1_Reserved1_61 : 13|3@1+ (1,0) [0|7] ""  DCDC
 SG_ M2D_CMD1_DCDCWrkMdSwtch_61 : 16|2@1+ (1,0) [0|3] ""  DCDC
 SG_ M2D_CMD1_DCDCWrkMdSet_61 : 18|2@1+ (1,0) [0|3] ""  DCDC
 SG_ M2D_CMD1_Reserved2_61 : 20|3@1+ (1,0) [0|7] ""  DCDC
 SG_ M2D_CMD1_DCDCOutputCrrntSet_61 : 23|16@1+ (0.05,-2000) [-2000|1276.75] "A"  DCDC
 SG_ M2D_CMD1_DCDCOutputVltge_Set_61 : 39|12@1+ (0.1,-200) [-200|209.5] "V"  DCDC
 SG_ M2D_CMD1_Reserved3_61 : 51|4@1+ (1,0) [0|15] ""  DCDC
 SG_ M2D_CMD1_CommunicationState_61 : 55|2@1+ (1,0) [0|3] ""  DCDC
 SG_ M2D_CMD1_DCDCFaultClear_61 : 57|1@1+ (1,0) [0|1] ""  DCDC
 SG_ M2D_CMD1_PCSOperationState_61 : 58|2@1+ (1,0) [0|3] ""  DCDC
 SG_ M2D_CMD1_DCDCLVoffControl_61 : 60|1@1+ (1,0) [0|1] ""  DCDC
 SG_ M2D_CMD1_Reserved4_61 : 61|2@1+ (1,0) [0|3] ""  DCDC

BO_ 2148827006 M2D_CMD1__62: 8 MBMU
 SG_ M2D_CMD1_CRC_62 : 0|8@1+ (1,0) [0|255] ""  DCDC
 SG_ M2D_CMD1_DCDCSerialNum_62 : 8|4@1+ (1,0) [0|15] ""  DCDC
 SG_ M2D_CMD1_DCDCEnable_62 : 12|1@1+ (1,0) [0|1] ""  DCDC
 SG_ M2D_CMD1_Reserved1_62 : 13|3@1+ (1,0) [0|7] ""  DCDC
 SG_ M2D_CMD1_DCDCWrkMdSwtch_62 : 16|2@1+ (1,0) [0|3] ""  DCDC
 SG_ M2D_CMD1_DCDCWrkMdSet_62 : 18|2@1+ (1,0) [0|3] ""  DCDC
 SG_ M2D_CMD1_Reserved2_62 : 20|3@1+ (1,0) [0|7] ""  DCDC
 SG_ M2D_CMD1_DCDCOutputCrrntSet_62 : 23|16@1+ (0.05,-2000) [-2000|1276.75] "A"  DCDC
 SG_ M2D_CMD1_DCDCOutputVltge_Set_62 : 39|12@1+ (0.1,-200) [-200|209.5] "V"  DCDC
 SG_ M2D_CMD1_Reserved3_62 : 51|4@1+ (1,0) [0|15] ""  DCDC
 SG_ M2D_CMD1_CommunicationState_62 : 55|2@1+ (1,0) [0|3] ""  DCDC
 SG_ M2D_CMD1_DCDCFaultClear_62 : 57|1@1+ (1,0) [0|1] ""  DCDC
 SG_ M2D_CMD1_PCSOperationState_62 : 58|2@1+ (1,0) [0|3] ""  DCDC
 SG_ M2D_CMD1_DCDCLVoffControl_62 : 60|1@1+ (1,0) [0|1] ""  DCDC
 SG_ M2D_CMD1_Reserved4_62 : 61|2@1+ (1,0) [0|3] ""  DCDC

BO_ 2148827007 M2D_CMD1__63: 8 MBMU
 SG_ M2D_CMD1_CRC_63 : 0|8@1+ (1,0) [0|255] ""  DCDC
 SG_ M2D_CMD1_DCDCSerialNum_63 : 8|4@1+ (1,0) [0|15] ""  DCDC
 SG_ M2D_CMD1_DCDCEnable_63 : 12|1@1+ (1,0) [0|1] ""  DCDC
 SG_ M2D_CMD1_Reserved1_63 : 13|3@1+ (1,0) [0|7] ""  DCDC
 SG_ M2D_CMD1_DCDCWrkMdSwtch_63 : 16|2@1+ (1,0) [0|3] ""  DCDC
 SG_ M2D_CMD1_DCDCWrkMdSet_63 : 18|2@1+ (1,0) [0|3] ""  DCDC
 SG_ M2D_CMD1_Reserved2_63 : 20|3@1+ (1,0) [0|7] ""  DCDC
 SG_ M2D_CMD1_DCDCOutputCrrntSet_63 : 23|16@1+ (0.05,-2000) [-2000|1276.75] "A"  DCDC
 SG_ M2D_CMD1_DCDCOutputVltge_Set_63 : 39|12@1+ (0.1,-200) [-200|209.5] "V"  DCDC
 SG_ M2D_CMD1_Reserved3_63 : 51|4@1+ (1,0) [0|15] ""  DCDC
 SG_ M2D_CMD1_CommunicationState_63 : 55|2@1+ (1,0) [0|3] ""  DCDC
 SG_ M2D_CMD1_DCDCFaultClear_63 : 57|1@1+ (1,0) [0|1] ""  DCDC
 SG_ M2D_CMD1_PCSOperationState_63 : 58|2@1+ (1,0) [0|3] ""  DCDC
 SG_ M2D_CMD1_DCDCLVoffControl_63 : 60|1@1+ (1,0) [0|1] ""  DCDC
 SG_ M2D_CMD1_Reserved4_63 : 61|2@1+ (1,0) [0|3] ""  DCDC

BO_ 2148892481 M2D_CMD2__01: 8 MBMU
 SG_ M2D_CMD2_CRC_01 : 0|8@1+ (1,0) [0|255] ""  DCDC
 SG_ M2D_IDX_CMD_Type_01 : 8|8@1+ (1,0) [0|255] ""  DCDC
 SG_ M2D_IDX_DCDC_Index_01 : 16|8@1+ (1,0) [0|255] ""  DCDC
 SG_ M2D_IDX_DCDC_Matchingcode_01 : 24|8@1+ (1,0) [0|255] ""  DCDC
 SG_ M2D_IDX_Reserved_01 : 32|32@1+ (1,0) [0|4294967295] ""  DCDC

BO_ 2148892482 M2D_CMD2__02: 8 MBMU
 SG_ M2D_CMD2_CRC_02 : 0|8@1+ (1,0) [0|255] ""  DCDC
 SG_ M2D_IDX_CMD_Type_02 : 8|8@1+ (1,0) [0|255] ""  DCDC
 SG_ M2D_IDX_DCDC_Index_02 : 16|8@1+ (1,0) [0|255] ""  DCDC
 SG_ M2D_IDX_DCDC_Matchingcode_02 : 24|8@1+ (1,0) [0|255] ""  DCDC
 SG_ M2D_IDX_Reserved_02 : 32|32@1+ (1,0) [0|4294967295] ""  DCDC

BO_ 2148892483 M2D_CMD2__03: 8 MBMU
 SG_ M2D_CMD2_CRC_03 : 0|8@1+ (1,0) [0|255] ""  DCDC
 SG_ M2D_IDX_CMD_Type_03 : 8|8@1+ (1,0) [0|255] ""  DCDC
 SG_ M2D_IDX_DCDC_Index_03 : 16|8@1+ (1,0) [0|255] ""  DCDC
 SG_ M2D_IDX_DCDC_Matchingcode_03 : 24|8@1+ (1,0) [0|255] ""  DCDC
 SG_ M2D_IDX_Reserved_03 : 32|32@1+ (1,0) [0|4294967295] ""  DCDC

BO_ 2148892484 M2D_CMD2__04: 8 MBMU
 SG_ M2D_CMD2_CRC_04 : 0|8@1+ (1,0) [0|255] ""  DCDC
 SG_ M2D_IDX_CMD_Type_04 : 8|8@1+ (1,0) [0|255] ""  DCDC
 SG_ M2D_IDX_DCDC_Index_04 : 16|8@1+ (1,0) [0|255] ""  DCDC
 SG_ M2D_IDX_DCDC_Matchingcode_04 : 24|8@1+ (1,0) [0|255] ""  DCDC
 SG_ M2D_IDX_Reserved_04 : 32|32@1+ (1,0) [0|4294967295] ""  DCDC

BO_ 2148892485 M2D_CMD2__05: 8 MBMU
 SG_ M2D_CMD2_CRC_05 : 0|8@1+ (1,0) [0|255] ""  DCDC
 SG_ M2D_IDX_CMD_Type_05 : 8|8@1+ (1,0) [0|255] ""  DCDC
 SG_ M2D_IDX_DCDC_Index_05 : 16|8@1+ (1,0) [0|255] ""  DCDC
 SG_ M2D_IDX_DCDC_Matchingcode_05 : 24|8@1+ (1,0) [0|255] ""  DCDC
 SG_ M2D_IDX_Reserved_05 : 32|32@1+ (1,0) [0|4294967295] ""  DCDC

BO_ 2148892486 M2D_CMD2__06: 8 MBMU
 SG_ M2D_CMD2_CRC_06 : 0|8@1+ (1,0) [0|255] ""  DCDC
 SG_ M2D_IDX_CMD_Type_06 : 8|8@1+ (1,0) [0|255] ""  DCDC
 SG_ M2D_IDX_DCDC_Index_06 : 16|8@1+ (1,0) [0|255] ""  DCDC
 SG_ M2D_IDX_DCDC_Matchingcode_06 : 24|8@1+ (1,0) [0|255] ""  DCDC
 SG_ M2D_IDX_Reserved_06 : 32|32@1+ (1,0) [0|4294967295] ""  DCDC

BO_ 2148892487 M2D_CMD2__07: 8 MBMU
 SG_ M2D_CMD2_CRC_07 : 0|8@1+ (1,0) [0|255] ""  DCDC
 SG_ M2D_IDX_CMD_Type_07 : 8|8@1+ (1,0) [0|255] ""  DCDC
 SG_ M2D_IDX_DCDC_Index_07 : 16|8@1+ (1,0) [0|255] ""  DCDC
 SG_ M2D_IDX_DCDC_Matchingcode_07 : 24|8@1+ (1,0) [0|255] ""  DCDC
 SG_ M2D_IDX_Reserved_07 : 32|32@1+ (1,0) [0|4294967295] ""  DCDC

BO_ 2148892488 M2D_CMD2__08: 8 MBMU
 SG_ M2D_CMD2_CRC_08 : 0|8@1+ (1,0) [0|255] ""  DCDC
 SG_ M2D_IDX_CMD_Type_08 : 8|8@1+ (1,0) [0|255] ""  DCDC
 SG_ M2D_IDX_DCDC_Index_08 : 16|8@1+ (1,0) [0|255] ""  DCDC
 SG_ M2D_IDX_DCDC_Matchingcode_08 : 24|8@1+ (1,0) [0|255] ""  DCDC
 SG_ M2D_IDX_Reserved_08 : 32|32@1+ (1,0) [0|4294967295] ""  DCDC

BO_ 2148892489 M2D_CMD2__09: 8 MBMU
 SG_ M2D_CMD2_CRC_09 : 0|8@1+ (1,0) [0|255] ""  DCDC
 SG_ M2D_IDX_CMD_Type_09 : 8|8@1+ (1,0) [0|255] ""  DCDC
 SG_ M2D_IDX_DCDC_Index_09 : 16|8@1+ (1,0) [0|255] ""  DCDC
 SG_ M2D_IDX_DCDC_Matchingcode_09 : 24|8@1+ (1,0) [0|255] ""  DCDC
 SG_ M2D_IDX_Reserved_09 : 32|32@1+ (1,0) [0|4294967295] ""  DCDC

BO_ 2148892490 M2D_CMD2__10: 8 MBMU
 SG_ M2D_CMD2_CRC_10 : 0|8@1+ (1,0) [0|255] ""  DCDC
 SG_ M2D_IDX_CMD_Type_10 : 8|8@1+ (1,0) [0|255] ""  DCDC
 SG_ M2D_IDX_DCDC_Index_10 : 16|8@1+ (1,0) [0|255] ""  DCDC
 SG_ M2D_IDX_DCDC_Matchingcode_10 : 24|8@1+ (1,0) [0|255] ""  DCDC
 SG_ M2D_IDX_Reserved_10 : 32|32@1+ (1,0) [0|4294967295] ""  DCDC

BO_ 2148892491 M2D_CMD2__11: 8 MBMU
 SG_ M2D_CMD2_CRC_11 : 0|8@1+ (1,0) [0|255] ""  DCDC
 SG_ M2D_IDX_CMD_Type_11 : 8|8@1+ (1,0) [0|255] ""  DCDC
 SG_ M2D_IDX_DCDC_Index_11 : 16|8@1+ (1,0) [0|255] ""  DCDC
 SG_ M2D_IDX_DCDC_Matchingcode_11 : 24|8@1+ (1,0) [0|255] ""  DCDC
 SG_ M2D_IDX_Reserved_11 : 32|32@1+ (1,0) [0|4294967295] ""  DCDC

BO_ 2148892492 M2D_CMD2__12: 8 MBMU
 SG_ M2D_CMD2_CRC_12 : 0|8@1+ (1,0) [0|255] ""  DCDC
 SG_ M2D_IDX_CMD_Type_12 : 8|8@1+ (1,0) [0|255] ""  DCDC
 SG_ M2D_IDX_DCDC_Index_12 : 16|8@1+ (1,0) [0|255] ""  DCDC
 SG_ M2D_IDX_DCDC_Matchingcode_12 : 24|8@1+ (1,0) [0|255] ""  DCDC
 SG_ M2D_IDX_Reserved_12 : 32|32@1+ (1,0) [0|4294967295] ""  DCDC

BO_ 2148892493 M2D_CMD2__13: 8 MBMU
 SG_ M2D_CMD2_CRC_13 : 0|8@1+ (1,0) [0|255] ""  DCDC
 SG_ M2D_IDX_CMD_Type_13 : 8|8@1+ (1,0) [0|255] ""  DCDC
 SG_ M2D_IDX_DCDC_Index_13 : 16|8@1+ (1,0) [0|255] ""  DCDC
 SG_ M2D_IDX_DCDC_Matchingcode_13 : 24|8@1+ (1,0) [0|255] ""  DCDC
 SG_ M2D_IDX_Reserved_13 : 32|32@1+ (1,0) [0|4294967295] ""  DCDC

BO_ 2148892494 M2D_CMD2__14: 8 MBMU
 SG_ M2D_CMD2_CRC_14 : 0|8@1+ (1,0) [0|255] ""  DCDC
 SG_ M2D_IDX_CMD_Type_14 : 8|8@1+ (1,0) [0|255] ""  DCDC
 SG_ M2D_IDX_DCDC_Index_14 : 16|8@1+ (1,0) [0|255] ""  DCDC
 SG_ M2D_IDX_DCDC_Matchingcode_14 : 24|8@1+ (1,0) [0|255] ""  DCDC
 SG_ M2D_IDX_Reserved_14 : 32|32@1+ (1,0) [0|4294967295] ""  DCDC

BO_ 2148892495 M2D_CMD2__15: 8 MBMU
 SG_ M2D_CMD2_CRC_15 : 0|8@1+ (1,0) [0|255] ""  DCDC
 SG_ M2D_IDX_CMD_Type_15 : 8|8@1+ (1,0) [0|255] ""  DCDC
 SG_ M2D_IDX_DCDC_Index_15 : 16|8@1+ (1,0) [0|255] ""  DCDC
 SG_ M2D_IDX_DCDC_Matchingcode_15 : 24|8@1+ (1,0) [0|255] ""  DCDC
 SG_ M2D_IDX_Reserved_15 : 32|32@1+ (1,0) [0|4294967295] ""  DCDC

BO_ 2148892496 M2D_CMD2__16: 8 MBMU
 SG_ M2D_CMD2_CRC_16 : 0|8@1+ (1,0) [0|255] ""  DCDC
 SG_ M2D_IDX_CMD_Type_16 : 8|8@1+ (1,0) [0|255] ""  DCDC
 SG_ M2D_IDX_DCDC_Index_16 : 16|8@1+ (1,0) [0|255] ""  DCDC
 SG_ M2D_IDX_DCDC_Matchingcode_16 : 24|8@1+ (1,0) [0|255] ""  DCDC
 SG_ M2D_IDX_Reserved_16 : 32|32@1+ (1,0) [0|4294967295] ""  DCDC

BO_ 2148892497 M2D_CMD2__17: 8 MBMU
 SG_ M2D_CMD2_CRC_17 : 0|8@1+ (1,0) [0|255] ""  DCDC
 SG_ M2D_IDX_CMD_Type_17 : 8|8@1+ (1,0) [0|255] ""  DCDC
 SG_ M2D_IDX_DCDC_Index_17 : 16|8@1+ (1,0) [0|255] ""  DCDC
 SG_ M2D_IDX_DCDC_Matchingcode_17 : 24|8@1+ (1,0) [0|255] ""  DCDC
 SG_ M2D_IDX_Reserved_17 : 32|32@1+ (1,0) [0|4294967295] ""  DCDC

BO_ 2148892498 M2D_CMD2__18: 8 MBMU
 SG_ M2D_CMD2_CRC_18 : 0|8@1+ (1,0) [0|255] ""  DCDC
 SG_ M2D_IDX_CMD_Type_18 : 8|8@1+ (1,0) [0|255] ""  DCDC
 SG_ M2D_IDX_DCDC_Index_18 : 16|8@1+ (1,0) [0|255] ""  DCDC
 SG_ M2D_IDX_DCDC_Matchingcode_18 : 24|8@1+ (1,0) [0|255] ""  DCDC
 SG_ M2D_IDX_Reserved_18 : 32|32@1+ (1,0) [0|4294967295] ""  DCDC

BO_ 2148892499 M2D_CMD2__19: 8 MBMU
 SG_ M2D_CMD2_CRC_19 : 0|8@1+ (1,0) [0|255] ""  DCDC
 SG_ M2D_IDX_CMD_Type_19 : 8|8@1+ (1,0) [0|255] ""  DCDC
 SG_ M2D_IDX_DCDC_Index_19 : 16|8@1+ (1,0) [0|255] ""  DCDC
 SG_ M2D_IDX_DCDC_Matchingcode_19 : 24|8@1+ (1,0) [0|255] ""  DCDC
 SG_ M2D_IDX_Reserved_19 : 32|32@1+ (1,0) [0|4294967295] ""  DCDC

BO_ 2148892500 M2D_CMD2__20: 8 MBMU
 SG_ M2D_CMD2_CRC_20 : 0|8@1+ (1,0) [0|255] ""  DCDC
 SG_ M2D_IDX_CMD_Type_20 : 8|8@1+ (1,0) [0|255] ""  DCDC
 SG_ M2D_IDX_DCDC_Index_20 : 16|8@1+ (1,0) [0|255] ""  DCDC
 SG_ M2D_IDX_DCDC_Matchingcode_20 : 24|8@1+ (1,0) [0|255] ""  DCDC
 SG_ M2D_IDX_Reserved_20 : 32|32@1+ (1,0) [0|4294967295] ""  DCDC

BO_ 2148892501 M2D_CMD2__21: 8 MBMU
 SG_ M2D_CMD2_CRC_21 : 0|8@1+ (1,0) [0|255] ""  DCDC
 SG_ M2D_IDX_CMD_Type_21 : 8|8@1+ (1,0) [0|255] ""  DCDC
 SG_ M2D_IDX_DCDC_Index_21 : 16|8@1+ (1,0) [0|255] ""  DCDC
 SG_ M2D_IDX_DCDC_Matchingcode_21 : 24|8@1+ (1,0) [0|255] ""  DCDC
 SG_ M2D_IDX_Reserved_21 : 32|32@1+ (1,0) [0|4294967295] ""  DCDC

BO_ 2148892502 M2D_CMD2__22: 8 MBMU
 SG_ M2D_CMD2_CRC_22 : 0|8@1+ (1,0) [0|255] ""  DCDC
 SG_ M2D_IDX_CMD_Type_22 : 8|8@1+ (1,0) [0|255] ""  DCDC
 SG_ M2D_IDX_DCDC_Index_22 : 16|8@1+ (1,0) [0|255] ""  DCDC
 SG_ M2D_IDX_DCDC_Matchingcode_22 : 24|8@1+ (1,0) [0|255] ""  DCDC
 SG_ M2D_IDX_Reserved_22 : 32|32@1+ (1,0) [0|4294967295] ""  DCDC

BO_ 2148892503 M2D_CMD2__23: 8 MBMU
 SG_ M2D_CMD2_CRC_23 : 0|8@1+ (1,0) [0|255] ""  DCDC
 SG_ M2D_IDX_CMD_Type_23 : 8|8@1+ (1,0) [0|255] ""  DCDC
 SG_ M2D_IDX_DCDC_Index_23 : 16|8@1+ (1,0) [0|255] ""  DCDC
 SG_ M2D_IDX_DCDC_Matchingcode_23 : 24|8@1+ (1,0) [0|255] ""  DCDC
 SG_ M2D_IDX_Reserved_23 : 32|32@1+ (1,0) [0|4294967295] ""  DCDC

BO_ 2148892504 M2D_CMD2__24: 8 MBMU
 SG_ M2D_CMD2_CRC_24 : 0|8@1+ (1,0) [0|255] ""  DCDC
 SG_ M2D_IDX_CMD_Type_24 : 8|8@1+ (1,0) [0|255] ""  DCDC
 SG_ M2D_IDX_DCDC_Index_24 : 16|8@1+ (1,0) [0|255] ""  DCDC
 SG_ M2D_IDX_DCDC_Matchingcode_24 : 24|8@1+ (1,0) [0|255] ""  DCDC
 SG_ M2D_IDX_Reserved_24 : 32|32@1+ (1,0) [0|4294967295] ""  DCDC

BO_ 2148892505 M2D_CMD2__25: 8 MBMU
 SG_ M2D_CMD2_CRC_25 : 0|8@1+ (1,0) [0|255] ""  DCDC
 SG_ M2D_IDX_CMD_Type_25 : 8|8@1+ (1,0) [0|255] ""  DCDC
 SG_ M2D_IDX_DCDC_Index_25 : 16|8@1+ (1,0) [0|255] ""  DCDC
 SG_ M2D_IDX_DCDC_Matchingcode_25 : 24|8@1+ (1,0) [0|255] ""  DCDC
 SG_ M2D_IDX_Reserved_25 : 32|32@1+ (1,0) [0|4294967295] ""  DCDC

BO_ 2148892506 M2D_CMD2__26: 8 MBMU
 SG_ M2D_CMD2_CRC_26 : 0|8@1+ (1,0) [0|255] ""  DCDC
 SG_ M2D_IDX_CMD_Type_26 : 8|8@1+ (1,0) [0|255] ""  DCDC
 SG_ M2D_IDX_DCDC_Index_26 : 16|8@1+ (1,0) [0|255] ""  DCDC
 SG_ M2D_IDX_DCDC_Matchingcode_26 : 24|8@1+ (1,0) [0|255] ""  DCDC
 SG_ M2D_IDX_Reserved_26 : 32|32@1+ (1,0) [0|4294967295] ""  DCDC

BO_ 2148892507 M2D_CMD2__27: 8 MBMU
 SG_ M2D_CMD2_CRC_27 : 0|8@1+ (1,0) [0|255] ""  DCDC
 SG_ M2D_IDX_CMD_Type_27 : 8|8@1+ (1,0) [0|255] ""  DCDC
 SG_ M2D_IDX_DCDC_Index_27 : 16|8@1+ (1,0) [0|255] ""  DCDC
 SG_ M2D_IDX_DCDC_Matchingcode_27 : 24|8@1+ (1,0) [0|255] ""  DCDC
 SG_ M2D_IDX_Reserved_27 : 32|32@1+ (1,0) [0|4294967295] ""  DCDC

BO_ 2148892508 M2D_CMD2__28: 8 MBMU
 SG_ M2D_CMD2_CRC_28 : 0|8@1+ (1,0) [0|255] ""  DCDC
 SG_ M2D_IDX_CMD_Type_28 : 8|8@1+ (1,0) [0|255] ""  DCDC
 SG_ M2D_IDX_DCDC_Index_28 : 16|8@1+ (1,0) [0|255] ""  DCDC
 SG_ M2D_IDX_DCDC_Matchingcode_28 : 24|8@1+ (1,0) [0|255] ""  DCDC
 SG_ M2D_IDX_Reserved_28 : 32|32@1+ (1,0) [0|4294967295] ""  DCDC

BO_ 2148892509 M2D_CMD2__29: 8 MBMU
 SG_ M2D_CMD2_CRC_29 : 0|8@1+ (1,0) [0|255] ""  DCDC
 SG_ M2D_IDX_CMD_Type_29 : 8|8@1+ (1,0) [0|255] ""  DCDC
 SG_ M2D_IDX_DCDC_Index_29 : 16|8@1+ (1,0) [0|255] ""  DCDC
 SG_ M2D_IDX_DCDC_Matchingcode_29 : 24|8@1+ (1,0) [0|255] ""  DCDC
 SG_ M2D_IDX_Reserved_29 : 32|32@1+ (1,0) [0|4294967295] ""  DCDC

BO_ 2148892510 M2D_CMD2__30: 8 MBMU
 SG_ M2D_CMD2_CRC_30 : 0|8@1+ (1,0) [0|255] ""  DCDC
 SG_ M2D_IDX_CMD_Type_30 : 8|8@1+ (1,0) [0|255] ""  DCDC
 SG_ M2D_IDX_DCDC_Index_30 : 16|8@1+ (1,0) [0|255] ""  DCDC
 SG_ M2D_IDX_DCDC_Matchingcode_30 : 24|8@1+ (1,0) [0|255] ""  DCDC
 SG_ M2D_IDX_Reserved_30 : 32|32@1+ (1,0) [0|4294967295] ""  DCDC

BO_ 2148892511 M2D_CMD2__31: 8 MBMU
 SG_ M2D_CMD2_CRC_31 : 0|8@1+ (1,0) [0|255] ""  DCDC
 SG_ M2D_IDX_CMD_Type_31 : 8|8@1+ (1,0) [0|255] ""  DCDC
 SG_ M2D_IDX_DCDC_Index_31 : 16|8@1+ (1,0) [0|255] ""  DCDC
 SG_ M2D_IDX_DCDC_Matchingcode_31 : 24|8@1+ (1,0) [0|255] ""  DCDC
 SG_ M2D_IDX_Reserved_31 : 32|32@1+ (1,0) [0|4294967295] ""  DCDC

BO_ 2148892512 M2D_CMD2__32: 8 MBMU
 SG_ M2D_CMD2_CRC_32 : 0|8@1+ (1,0) [0|255] ""  DCDC
 SG_ M2D_IDX_CMD_Type_32 : 8|8@1+ (1,0) [0|255] ""  DCDC
 SG_ M2D_IDX_DCDC_Index_32 : 16|8@1+ (1,0) [0|255] ""  DCDC
 SG_ M2D_IDX_DCDC_Matchingcode_32 : 24|8@1+ (1,0) [0|255] ""  DCDC
 SG_ M2D_IDX_Reserved_32 : 32|32@1+ (1,0) [0|4294967295] ""  DCDC

BO_ 2148892513 M2D_CMD2__33: 8 MBMU
 SG_ M2D_CMD2_CRC_33 : 0|8@1+ (1,0) [0|255] ""  DCDC
 SG_ M2D_IDX_CMD_Type_33 : 8|8@1+ (1,0) [0|255] ""  DCDC
 SG_ M2D_IDX_DCDC_Index_33 : 16|8@1+ (1,0) [0|255] ""  DCDC
 SG_ M2D_IDX_DCDC_Matchingcode_33 : 24|8@1+ (1,0) [0|255] ""  DCDC
 SG_ M2D_IDX_Reserved_33 : 32|32@1+ (1,0) [0|4294967295] ""  DCDC

BO_ 2148892514 M2D_CMD2__34: 8 MBMU
 SG_ M2D_CMD2_CRC_34 : 0|8@1+ (1,0) [0|255] ""  DCDC
 SG_ M2D_IDX_CMD_Type_34 : 8|8@1+ (1,0) [0|255] ""  DCDC
 SG_ M2D_IDX_DCDC_Index_34 : 16|8@1+ (1,0) [0|255] ""  DCDC
 SG_ M2D_IDX_DCDC_Matchingcode_34 : 24|8@1+ (1,0) [0|255] ""  DCDC
 SG_ M2D_IDX_Reserved_34 : 32|32@1+ (1,0) [0|4294967295] ""  DCDC

BO_ 2148892515 M2D_CMD2__35: 8 MBMU
 SG_ M2D_CMD2_CRC_35 : 0|8@1+ (1,0) [0|255] ""  DCDC
 SG_ M2D_IDX_CMD_Type_35 : 8|8@1+ (1,0) [0|255] ""  DCDC
 SG_ M2D_IDX_DCDC_Index_35 : 16|8@1+ (1,0) [0|255] ""  DCDC
 SG_ M2D_IDX_DCDC_Matchingcode_35 : 24|8@1+ (1,0) [0|255] ""  DCDC
 SG_ M2D_IDX_Reserved_35 : 32|32@1+ (1,0) [0|4294967295] ""  DCDC

BO_ 2148892516 M2D_CMD2__36: 8 MBMU
 SG_ M2D_CMD2_CRC_36 : 0|8@1+ (1,0) [0|255] ""  DCDC
 SG_ M2D_IDX_CMD_Type_36 : 8|8@1+ (1,0) [0|255] ""  DCDC
 SG_ M2D_IDX_DCDC_Index_36 : 16|8@1+ (1,0) [0|255] ""  DCDC
 SG_ M2D_IDX_DCDC_Matchingcode_36 : 24|8@1+ (1,0) [0|255] ""  DCDC
 SG_ M2D_IDX_Reserved_36 : 32|32@1+ (1,0) [0|4294967295] ""  DCDC

BO_ 2148892517 M2D_CMD2__37: 8 MBMU
 SG_ M2D_CMD2_CRC_37 : 0|8@1+ (1,0) [0|255] ""  DCDC
 SG_ M2D_IDX_CMD_Type_37 : 8|8@1+ (1,0) [0|255] ""  DCDC
 SG_ M2D_IDX_DCDC_Index_37 : 16|8@1+ (1,0) [0|255] ""  DCDC
 SG_ M2D_IDX_DCDC_Matchingcode_37 : 24|8@1+ (1,0) [0|255] ""  DCDC
 SG_ M2D_IDX_Reserved_37 : 32|32@1+ (1,0) [0|4294967295] ""  DCDC

BO_ 2148892518 M2D_CMD2__38: 8 MBMU
 SG_ M2D_CMD2_CRC_38 : 0|8@1+ (1,0) [0|255] ""  DCDC
 SG_ M2D_IDX_CMD_Type_38 : 8|8@1+ (1,0) [0|255] ""  DCDC
 SG_ M2D_IDX_DCDC_Index_38 : 16|8@1+ (1,0) [0|255] ""  DCDC
 SG_ M2D_IDX_DCDC_Matchingcode_38 : 24|8@1+ (1,0) [0|255] ""  DCDC
 SG_ M2D_IDX_Reserved_38 : 32|32@1+ (1,0) [0|4294967295] ""  DCDC

BO_ 2148892519 M2D_CMD2__39: 8 MBMU
 SG_ M2D_CMD2_CRC_39 : 0|8@1+ (1,0) [0|255] ""  DCDC
 SG_ M2D_IDX_CMD_Type_39 : 8|8@1+ (1,0) [0|255] ""  DCDC
 SG_ M2D_IDX_DCDC_Index_39 : 16|8@1+ (1,0) [0|255] ""  DCDC
 SG_ M2D_IDX_DCDC_Matchingcode_39 : 24|8@1+ (1,0) [0|255] ""  DCDC
 SG_ M2D_IDX_Reserved_39 : 32|32@1+ (1,0) [0|4294967295] ""  DCDC

BO_ 2148892520 M2D_CMD2__40: 8 MBMU
 SG_ M2D_CMD2_CRC_40 : 0|8@1+ (1,0) [0|255] ""  DCDC
 SG_ M2D_IDX_CMD_Type_40 : 8|8@1+ (1,0) [0|255] ""  DCDC
 SG_ M2D_IDX_DCDC_Index_40 : 16|8@1+ (1,0) [0|255] ""  DCDC
 SG_ M2D_IDX_DCDC_Matchingcode_40 : 24|8@1+ (1,0) [0|255] ""  DCDC
 SG_ M2D_IDX_Reserved_40 : 32|32@1+ (1,0) [0|4294967295] ""  DCDC

CM_ SG_ 2148826952 M2D_CMD1_CRC_08 "CRC校验";
CM_ SG_ 2148826952 M2D_CMD1_DCDCSerialNum_08 "预留  （DCDC编号）";
CM_ SG_ 2148826952 M2D_CMD1_DCDCEnable_08 "使能DCDC命令";
CM_ SG_ 2148826952 M2D_CMD1_Reserved1_08 "预留1";
CM_ SG_ 2148826952 M2D_CMD1_DCDCWrkMdSwtch_08 "DCDC工作状态切换";
CM_ SG_ 2148826952 M2D_CMD1_DCDCWrkMdSet_08 "DCDC工作模式设定";
CM_ SG_ 2148826952 M2D_CMD1_Reserved2_08 "预留2";
CM_ SG_ 2148826952 M2D_CMD1_DCDCOutputCrrntSet_08 "电池电流设定（放正充负）
电池电流=DC低压端电流+DC高压端电流";
CM_ SG_ 2148826952 M2D_CMD1_DCDCOutputVltge_Set_08 "DCDC输出电压设定";
CM_ SG_ 2148826952 M2D_CMD1_Reserved3_08 "预留3";
CM_ SG_ 2148826952 M2D_CMD1_CommunicationState_08 "MBMU与DCDC通讯状态";
CM_ SG_ 2148826952 M2D_CMD1_DCDCFaultClear_08 "DCDC故障清除指令";
CM_ SG_ 2148826952 M2D_CMD1_PCSOperationState_08 "PCS运行状态（预留）";
CM_ SG_ 2148826952 M2D_CMD1_DCDCLVoffControl_08 "DCDC低压下电控制";
CM_ SG_ 2148826952 M2D_CMD1_Reserved4_08 "预留4";
CM_ SG_ 2148826953 M2D_CMD1_CRC_09 "CRC校验";
CM_ SG_ 2148826953 M2D_CMD1_DCDCSerialNum_09 "预留  （DCDC编号）";
CM_ SG_ 2148826953 M2D_CMD1_DCDCEnable_09 "使能DCDC命令";
CM_ SG_ 2148826953 M2D_CMD1_Reserved1_09 "预留1";
CM_ SG_ 2148826953 M2D_CMD1_DCDCWrkMdSwtch_09 "DCDC工作状态切换";
CM_ SG_ 2148826953 M2D_CMD1_DCDCWrkMdSet_09 "DCDC工作模式设定";
CM_ SG_ 2148826953 M2D_CMD1_Reserved2_09 "预留2";
CM_ SG_ 2148826953 M2D_CMD1_DCDCOutputCrrntSet_09 "电池电流设定（放正充负）
电池电流=DC低压端电流+DC高压端电流";
CM_ SG_ 2148826953 M2D_CMD1_DCDCOutputVltge_Set_09 "DCDC输出电压设定";
CM_ SG_ 2148826953 M2D_CMD1_Reserved3_09 "预留3";
CM_ SG_ 2148826953 M2D_CMD1_CommunicationState_09 "MBMU与DCDC通讯状态";
CM_ SG_ 2148826953 M2D_CMD1_DCDCFaultClear_09 "DCDC故障清除指令";
CM_ SG_ 2148826953 M2D_CMD1_PCSOperationState_09 "PCS运行状态（预留）";
CM_ SG_ 2148826953 M2D_CMD1_DCDCLVoffControl_09 "DCDC低压下电控制";
CM_ SG_ 2148826953 M2D_CMD1_Reserved4_09 "预留4";
CM_ SG_ 2148826954 M2D_CMD1_CRC_10 "CRC校验";
CM_ SG_ 2148826954 M2D_CMD1_DCDCSerialNum_10 "预留  （DCDC编号）";
CM_ SG_ 2148826954 M2D_CMD1_DCDCEnable_10 "使能DCDC命令";
CM_ SG_ 2148826954 M2D_CMD1_Reserved1_10 "预留1";
CM_ SG_ 2148826954 M2D_CMD1_DCDCWrkMdSwtch_10 "DCDC工作状态切换";
CM_ SG_ 2148826954 M2D_CMD1_DCDCWrkMdSet_10 "DCDC工作模式设定";
CM_ SG_ 2148826954 M2D_CMD1_Reserved2_10 "预留2";
CM_ SG_ 2148826954 M2D_CMD1_DCDCOutputCrrntSet_10 "电池电流设定（放正充负）
电池电流=DC低压端电流+DC高压端电流";
CM_ SG_ 2148826954 M2D_CMD1_DCDCOutputVltge_Set_10 "DCDC输出电压设定";
CM_ SG_ 2148826954 M2D_CMD1_Reserved3_10 "预留3";
CM_ SG_ 2148826954 M2D_CMD1_CommunicationState_10 "MBMU与DCDC通讯状态";
CM_ SG_ 2148826954 M2D_CMD1_DCDCFaultClear_10 "DCDC故障清除指令";
CM_ SG_ 2148826954 M2D_CMD1_PCSOperationState_10 "PCS运行状态（预留）";
CM_ SG_ 2148826954 M2D_CMD1_DCDCLVoffControl_10 "DCDC低压下电控制";
CM_ SG_ 2148826954 M2D_CMD1_Reserved4_10 "预留4";
CM_ SG_ 2148826955 M2D_CMD1_CRC_11 "CRC校验";
CM_ SG_ 2148826955 M2D_CMD1_DCDCSerialNum_11 "预留  （DCDC编号）";
CM_ SG_ 2148826955 M2D_CMD1_DCDCEnable_11 "使能DCDC命令";
CM_ SG_ 2148826955 M2D_CMD1_Reserved1_11 "预留1";
CM_ SG_ 2148826955 M2D_CMD1_DCDCWrkMdSwtch_11 "DCDC工作状态切换";
CM_ SG_ 2148826955 M2D_CMD1_DCDCWrkMdSet_11 "DCDC工作模式设定";
CM_ SG_ 2148826955 M2D_CMD1_Reserved2_11 "预留2";
CM_ SG_ 2148826955 M2D_CMD1_DCDCOutputCrrntSet_11 "电池电流设定（放正充负）
电池电流=DC低压端电流+DC高压端电流";
CM_ SG_ 2148826955 M2D_CMD1_DCDCOutputVltge_Set_11 "DCDC输出电压设定";
CM_ SG_ 2148826955 M2D_CMD1_Reserved3_11 "预留3";
CM_ SG_ 2148826955 M2D_CMD1_CommunicationState_11 "MBMU与DCDC通讯状态";
CM_ SG_ 2148826955 M2D_CMD1_DCDCFaultClear_11 "DCDC故障清除指令";
CM_ SG_ 2148826955 M2D_CMD1_PCSOperationState_11 "PCS运行状态（预留）";
CM_ SG_ 2148826955 M2D_CMD1_DCDCLVoffControl_11 "DCDC低压下电控制";
CM_ SG_ 2148826955 M2D_CMD1_Reserved4_11 "预留4";
CM_ SG_ 2148826956 M2D_CMD1_CRC_12 "CRC校验";
CM_ SG_ 2148826956 M2D_CMD1_DCDCSerialNum_12 "预留  （DCDC编号）";
CM_ SG_ 2148826956 M2D_CMD1_DCDCEnable_12 "使能DCDC命令";
CM_ SG_ 2148826956 M2D_CMD1_Reserved1_12 "预留1";
CM_ SG_ 2148826956 M2D_CMD1_DCDCWrkMdSwtch_12 "DCDC工作状态切换";
CM_ SG_ 2148826956 M2D_CMD1_DCDCWrkMdSet_12 "DCDC工作模式设定";
CM_ SG_ 2148826956 M2D_CMD1_Reserved2_12 "预留2";
CM_ SG_ 2148826956 M2D_CMD1_DCDCOutputCrrntSet_12 "电池电流设定（放正充负）
电池电流=DC低压端电流+DC高压端电流";
CM_ SG_ 2148826956 M2D_CMD1_DCDCOutputVltge_Set_12 "DCDC输出电压设定";
CM_ SG_ 2148826956 M2D_CMD1_Reserved3_12 "预留3";
CM_ SG_ 2148826956 M2D_CMD1_CommunicationState_12 "MBMU与DCDC通讯状态";
CM_ SG_ 2148826956 M2D_CMD1_DCDCFaultClear_12 "DCDC故障清除指令";
CM_ SG_ 2148826956 M2D_CMD1_PCSOperationState_12 "PCS运行状态（预留）";
CM_ SG_ 2148826956 M2D_CMD1_DCDCLVoffControl_12 "DCDC低压下电控制";
CM_ SG_ 2148826956 M2D_CMD1_Reserved4_12 "预留4";
CM_ SG_ 2148826957 M2D_CMD1_CRC_13 "CRC校验";
CM_ SG_ 2148826957 M2D_CMD1_DCDCSerialNum_13 "预留  （DCDC编号）";
CM_ SG_ 2148826957 M2D_CMD1_DCDCEnable_13 "使能DCDC命令";
CM_ SG_ 2148826957 M2D_CMD1_Reserved1_13 "预留1";
CM_ SG_ 2148826957 M2D_CMD1_DCDCWrkMdSwtch_13 "DCDC工作状态切换";
CM_ SG_ 2148826957 M2D_CMD1_DCDCWrkMdSet_13 "DCDC工作模式设定";
CM_ SG_ 2148826957 M2D_CMD1_Reserved2_13 "预留2";
CM_ SG_ 2148826957 M2D_CMD1_DCDCOutputCrrntSet_13 "电池电流设定（放正充负）
电池电流=DC低压端电流+DC高压端电流";
CM_ SG_ 2148826957 M2D_CMD1_DCDCOutputVltge_Set_13 "DCDC输出电压设定";
CM_ SG_ 2148826957 M2D_CMD1_Reserved3_13 "预留3";
CM_ SG_ 2148826957 M2D_CMD1_CommunicationState_13 "MBMU与DCDC通讯状态";
CM_ SG_ 2148826957 M2D_CMD1_DCDCFaultClear_13 "DCDC故障清除指令";
CM_ SG_ 2148826957 M2D_CMD1_PCSOperationState_13 "PCS运行状态（预留）";
CM_ SG_ 2148826957 M2D_CMD1_DCDCLVoffControl_13 "DCDC低压下电控制";
CM_ SG_ 2148826957 M2D_CMD1_Reserved4_13 "预留4";
CM_ SG_ 2148826958 M2D_CMD1_CRC_14 "CRC校验";
CM_ SG_ 2148826958 M2D_CMD1_DCDCSerialNum_14 "预留  （DCDC编号）";
CM_ SG_ 2148826958 M2D_CMD1_DCDCEnable_14 "使能DCDC命令";
CM_ SG_ 2148826958 M2D_CMD1_Reserved1_14 "预留1";
CM_ SG_ 2148826958 M2D_CMD1_DCDCWrkMdSwtch_14 "DCDC工作状态切换";
CM_ SG_ 2148826958 M2D_CMD1_DCDCWrkMdSet_14 "DCDC工作模式设定";
CM_ SG_ 2148826958 M2D_CMD1_Reserved2_14 "预留2";
CM_ SG_ 2148826958 M2D_CMD1_DCDCOutputCrrntSet_14 "电池电流设定（放正充负）
电池电流=DC低压端电流+DC高压端电流";
CM_ SG_ 2148826958 M2D_CMD1_DCDCOutputVltge_Set_14 "DCDC输出电压设定";
CM_ SG_ 2148826958 M2D_CMD1_Reserved3_14 "预留3";
CM_ SG_ 2148826958 M2D_CMD1_CommunicationState_14 "MBMU与DCDC通讯状态";
CM_ SG_ 2148826958 M2D_CMD1_DCDCFaultClear_14 "DCDC故障清除指令";
CM_ SG_ 2148826958 M2D_CMD1_PCSOperationState_14 "PCS运行状态（预留）";
CM_ SG_ 2148826958 M2D_CMD1_DCDCLVoffControl_14 "DCDC低压下电控制";
CM_ SG_ 2148826958 M2D_CMD1_Reserved4_14 "预留4";
CM_ SG_ 2148826959 M2D_CMD1_CRC_15 "CRC校验";
CM_ SG_ 2148826959 M2D_CMD1_DCDCSerialNum_15 "预留  （DCDC编号）";
CM_ SG_ 2148826959 M2D_CMD1_DCDCEnable_15 "使能DCDC命令";
CM_ SG_ 2148826959 M2D_CMD1_Reserved1_15 "预留1";
CM_ SG_ 2148826959 M2D_CMD1_DCDCWrkMdSwtch_15 "DCDC工作状态切换";
CM_ SG_ 2148826959 M2D_CMD1_DCDCWrkMdSet_15 "DCDC工作模式设定";
CM_ SG_ 2148826959 M2D_CMD1_Reserved2_15 "预留2";
CM_ SG_ 2148826959 M2D_CMD1_DCDCOutputCrrntSet_15 "电池电流设定（放正充负）
电池电流=DC低压端电流+DC高压端电流";
CM_ SG_ 2148826959 M2D_CMD1_DCDCOutputVltge_Set_15 "DCDC输出电压设定";
CM_ SG_ 2148826959 M2D_CMD1_Reserved3_15 "预留3";
CM_ SG_ 2148826959 M2D_CMD1_CommunicationState_15 "MBMU与DCDC通讯状态";
CM_ SG_ 2148826959 M2D_CMD1_DCDCFaultClear_15 "DCDC故障清除指令";
CM_ SG_ 2148826959 M2D_CMD1_PCSOperationState_15 "PCS运行状态（预留）";
CM_ SG_ 2148826959 M2D_CMD1_DCDCLVoffControl_15 "DCDC低压下电控制";
CM_ SG_ 2148826959 M2D_CMD1_Reserved4_15 "预留4";
CM_ SG_ 2148826960 M2D_CMD1_CRC_16 "CRC校验";
CM_ SG_ 2148826960 M2D_CMD1_DCDCSerialNum_16 "预留  （DCDC编号）";
CM_ SG_ 2148826960 M2D_CMD1_DCDCEnable_16 "使能DCDC命令";
CM_ SG_ 2148826960 M2D_CMD1_Reserved1_16 "预留1";
CM_ SG_ 2148826960 M2D_CMD1_DCDCWrkMdSwtch_16 "DCDC工作状态切换";
CM_ SG_ 2148826960 M2D_CMD1_DCDCWrkMdSet_16 "DCDC工作模式设定";
CM_ SG_ 2148826960 M2D_CMD1_Reserved2_16 "预留2";
CM_ SG_ 2148826960 M2D_CMD1_DCDCOutputCrrntSet_16 "电池电流设定（放正充负）
电池电流=DC低压端电流+DC高压端电流";
CM_ SG_ 2148826960 M2D_CMD1_DCDCOutputVltge_Set_16 "DCDC输出电压设定";
CM_ SG_ 2148826960 M2D_CMD1_Reserved3_16 "预留3";
CM_ SG_ 2148826960 M2D_CMD1_CommunicationState_16 "MBMU与DCDC通讯状态";
CM_ SG_ 2148826960 M2D_CMD1_DCDCFaultClear_16 "DCDC故障清除指令";
CM_ SG_ 2148826960 M2D_CMD1_PCSOperationState_16 "PCS运行状态（预留）";
CM_ SG_ 2148826960 M2D_CMD1_DCDCLVoffControl_16 "DCDC低压下电控制";
CM_ SG_ 2148826960 M2D_CMD1_Reserved4_16 "预留4";
CM_ SG_ 2148826961 M2D_CMD1_CRC_17 "CRC校验";
CM_ SG_ 2148826961 M2D_CMD1_DCDCSerialNum_17 "预留  （DCDC编号）";
CM_ SG_ 2148826961 M2D_CMD1_DCDCEnable_17 "使能DCDC命令";
CM_ SG_ 2148826961 M2D_CMD1_Reserved1_17 "预留1";
CM_ SG_ 2148826961 M2D_CMD1_DCDCWrkMdSwtch_17 "DCDC工作状态切换";
CM_ SG_ 2148826961 M2D_CMD1_DCDCWrkMdSet_17 "DCDC工作模式设定";
CM_ SG_ 2148826961 M2D_CMD1_Reserved2_17 "预留2";
CM_ SG_ 2148826961 M2D_CMD1_DCDCOutputCrrntSet_17 "电池电流设定（放正充负）
电池电流=DC低压端电流+DC高压端电流";
CM_ SG_ 2148826961 M2D_CMD1_DCDCOutputVltge_Set_17 "DCDC输出电压设定";
CM_ SG_ 2148826961 M2D_CMD1_Reserved3_17 "预留3";
CM_ SG_ 2148826961 M2D_CMD1_CommunicationState_17 "MBMU与DCDC通讯状态";
CM_ SG_ 2148826961 M2D_CMD1_DCDCFaultClear_17 "DCDC故障清除指令";
CM_ SG_ 2148826961 M2D_CMD1_PCSOperationState_17 "PCS运行状态（预留）";
CM_ SG_ 2148826961 M2D_CMD1_DCDCLVoffControl_17 "DCDC低压下电控制";
CM_ SG_ 2148826961 M2D_CMD1_Reserved4_17 "预留4";
CM_ SG_ 2148826962 M2D_CMD1_CRC_18 "CRC校验";
CM_ SG_ 2148826962 M2D_CMD1_DCDCSerialNum_18 "预留  （DCDC编号）";
CM_ SG_ 2148826962 M2D_CMD1_DCDCEnable_18 "使能DCDC命令";
CM_ SG_ 2148826962 M2D_CMD1_Reserved1_18 "预留1";
CM_ SG_ 2148826962 M2D_CMD1_DCDCWrkMdSwtch_18 "DCDC工作状态切换";
CM_ SG_ 2148826962 M2D_CMD1_DCDCWrkMdSet_18 "DCDC工作模式设定";
CM_ SG_ 2148826962 M2D_CMD1_Reserved2_18 "预留2";
CM_ SG_ 2148826962 M2D_CMD1_DCDCOutputCrrntSet_18 "电池电流设定（放正充负）
电池电流=DC低压端电流+DC高压端电流";
CM_ SG_ 2148826962 M2D_CMD1_DCDCOutputVltge_Set_18 "DCDC输出电压设定";
CM_ SG_ 2148826962 M2D_CMD1_Reserved3_18 "预留3";
CM_ SG_ 2148826962 M2D_CMD1_CommunicationState_18 "MBMU与DCDC通讯状态";
CM_ SG_ 2148826962 M2D_CMD1_DCDCFaultClear_18 "DCDC故障清除指令";
CM_ SG_ 2148826962 M2D_CMD1_PCSOperationState_18 "PCS运行状态（预留）";
CM_ SG_ 2148826962 M2D_CMD1_DCDCLVoffControl_18 "DCDC低压下电控制";
CM_ SG_ 2148826962 M2D_CMD1_Reserved4_18 "预留4";
CM_ SG_ 2148826963 M2D_CMD1_CRC_19 "CRC校验";
CM_ SG_ 2148826963 M2D_CMD1_DCDCSerialNum_19 "预留  （DCDC编号）";
CM_ SG_ 2148826963 M2D_CMD1_DCDCEnable_19 "使能DCDC命令";
CM_ SG_ 2148826963 M2D_CMD1_Reserved1_19 "预留1";
CM_ SG_ 2148826963 M2D_CMD1_DCDCWrkMdSwtch_19 "DCDC工作状态切换";
CM_ SG_ 2148826963 M2D_CMD1_DCDCWrkMdSet_19 "DCDC工作模式设定";
CM_ SG_ 2148826963 M2D_CMD1_Reserved2_19 "预留2";
CM_ SG_ 2148826963 M2D_CMD1_DCDCOutputCrrntSet_19 "电池电流设定（放正充负）
电池电流=DC低压端电流+DC高压端电流";
CM_ SG_ 2148826963 M2D_CMD1_DCDCOutputVltge_Set_19 "DCDC输出电压设定";
CM_ SG_ 2148826963 M2D_CMD1_Reserved3_19 "预留3";
CM_ SG_ 2148826963 M2D_CMD1_CommunicationState_19 "MBMU与DCDC通讯状态";
CM_ SG_ 2148826963 M2D_CMD1_DCDCFaultClear_19 "DCDC故障清除指令";
CM_ SG_ 2148826963 M2D_CMD1_PCSOperationState_19 "PCS运行状态（预留）";
CM_ SG_ 2148826963 M2D_CMD1_DCDCLVoffControl_19 "DCDC低压下电控制";
CM_ SG_ 2148826963 M2D_CMD1_Reserved4_19 "预留4";
CM_ SG_ 2148826964 M2D_CMD1_CRC_20 "CRC校验";
CM_ SG_ 2148826964 M2D_CMD1_DCDCSerialNum_20 "预留  （DCDC编号）";
CM_ SG_ 2148826964 M2D_CMD1_DCDCEnable_20 "使能DCDC命令";
CM_ SG_ 2148826964 M2D_CMD1_Reserved1_20 "预留1";
CM_ SG_ 2148826964 M2D_CMD1_DCDCWrkMdSwtch_20 "DCDC工作状态切换";
CM_ SG_ 2148826964 M2D_CMD1_DCDCWrkMdSet_20 "DCDC工作模式设定";
CM_ SG_ 2148826964 M2D_CMD1_Reserved2_20 "预留2";
CM_ SG_ 2148826964 M2D_CMD1_DCDCOutputCrrntSet_20 "电池电流设定（放正充负）
电池电流=DC低压端电流+DC高压端电流";
CM_ SG_ 2148826964 M2D_CMD1_DCDCOutputVltge_Set_20 "DCDC输出电压设定";
CM_ SG_ 2148826964 M2D_CMD1_Reserved3_20 "预留3";
CM_ SG_ 2148826964 M2D_CMD1_CommunicationState_20 "MBMU与DCDC通讯状态";
CM_ SG_ 2148826964 M2D_CMD1_DCDCFaultClear_20 "DCDC故障清除指令";
CM_ SG_ 2148826964 M2D_CMD1_PCSOperationState_20 "PCS运行状态（预留）";
CM_ SG_ 2148826964 M2D_CMD1_DCDCLVoffControl_20 "DCDC低压下电控制";
CM_ SG_ 2148826964 M2D_CMD1_Reserved4_20 "预留4";
CM_ SG_ 2148826965 M2D_CMD1_CRC_21 "CRC校验";
CM_ SG_ 2148826965 M2D_CMD1_DCDCSerialNum_21 "预留  （DCDC编号）";
CM_ SG_ 2148826965 M2D_CMD1_DCDCEnable_21 "使能DCDC命令";
CM_ SG_ 2148826965 M2D_CMD1_Reserved1_21 "预留1";
CM_ SG_ 2148826965 M2D_CMD1_DCDCWrkMdSwtch_21 "DCDC工作状态切换";
CM_ SG_ 2148826965 M2D_CMD1_DCDCWrkMdSet_21 "DCDC工作模式设定";
CM_ SG_ 2148826965 M2D_CMD1_Reserved2_21 "预留2";
CM_ SG_ 2148826965 M2D_CMD1_DCDCOutputCrrntSet_21 "电池电流设定（放正充负）
电池电流=DC低压端电流+DC高压端电流";
CM_ SG_ 2148826965 M2D_CMD1_DCDCOutputVltge_Set_21 "DCDC输出电压设定";
CM_ SG_ 2148826965 M2D_CMD1_Reserved3_21 "预留3";
CM_ SG_ 2148826965 M2D_CMD1_CommunicationState_21 "MBMU与DCDC通讯状态";
CM_ SG_ 2148826965 M2D_CMD1_DCDCFaultClear_21 "DCDC故障清除指令";
CM_ SG_ 2148826965 M2D_CMD1_PCSOperationState_21 "PCS运行状态（预留）";
CM_ SG_ 2148826965 M2D_CMD1_DCDCLVoffControl_21 "DCDC低压下电控制";
CM_ SG_ 2148826965 M2D_CMD1_Reserved4_21 "预留4";
CM_ SG_ 2148826966 M2D_CMD1_CRC_22 "CRC校验";
CM_ SG_ 2148826966 M2D_CMD1_DCDCSerialNum_22 "预留  （DCDC编号）";
CM_ SG_ 2148826966 M2D_CMD1_DCDCEnable_22 "使能DCDC命令";
CM_ SG_ 2148826966 M2D_CMD1_Reserved1_22 "预留1";
CM_ SG_ 2148826966 M2D_CMD1_DCDCWrkMdSwtch_22 "DCDC工作状态切换";
CM_ SG_ 2148826966 M2D_CMD1_DCDCWrkMdSet_22 "DCDC工作模式设定";
CM_ SG_ 2148826966 M2D_CMD1_Reserved2_22 "预留2";
CM_ SG_ 2148826966 M2D_CMD1_DCDCOutputCrrntSet_22 "电池电流设定（放正充负）
电池电流=DC低压端电流+DC高压端电流";
CM_ SG_ 2148826966 M2D_CMD1_DCDCOutputVltge_Set_22 "DCDC输出电压设定";
CM_ SG_ 2148826966 M2D_CMD1_Reserved3_22 "预留3";
CM_ SG_ 2148826966 M2D_CMD1_CommunicationState_22 "MBMU与DCDC通讯状态";
CM_ SG_ 2148826966 M2D_CMD1_DCDCFaultClear_22 "DCDC故障清除指令";
CM_ SG_ 2148826966 M2D_CMD1_PCSOperationState_22 "PCS运行状态（预留）";
CM_ SG_ 2148826966 M2D_CMD1_DCDCLVoffControl_22 "DCDC低压下电控制";
CM_ SG_ 2148826966 M2D_CMD1_Reserved4_22 "预留4";
CM_ SG_ 2148826967 M2D_CMD1_CRC_23 "CRC校验";
CM_ SG_ 2148826967 M2D_CMD1_DCDCSerialNum_23 "预留  （DCDC编号）";
CM_ SG_ 2148826967 M2D_CMD1_DCDCEnable_23 "使能DCDC命令";
CM_ SG_ 2148826967 M2D_CMD1_Reserved1_23 "预留1";
CM_ SG_ 2148826967 M2D_CMD1_DCDCWrkMdSwtch_23 "DCDC工作状态切换";
CM_ SG_ 2148826967 M2D_CMD1_DCDCWrkMdSet_23 "DCDC工作模式设定";
CM_ SG_ 2148826967 M2D_CMD1_Reserved2_23 "预留2";
CM_ SG_ 2148826967 M2D_CMD1_DCDCOutputCrrntSet_23 "电池电流设定（放正充负）
电池电流=DC低压端电流+DC高压端电流";
CM_ SG_ 2148826967 M2D_CMD1_DCDCOutputVltge_Set_23 "DCDC输出电压设定";
CM_ SG_ 2148826967 M2D_CMD1_Reserved3_23 "预留3";
CM_ SG_ 2148826967 M2D_CMD1_CommunicationState_23 "MBMU与DCDC通讯状态";
CM_ SG_ 2148826967 M2D_CMD1_DCDCFaultClear_23 "DCDC故障清除指令";
CM_ SG_ 2148826967 M2D_CMD1_PCSOperationState_23 "PCS运行状态（预留）";
CM_ SG_ 2148826967 M2D_CMD1_DCDCLVoffControl_23 "DCDC低压下电控制";
CM_ SG_ 2148826967 M2D_CMD1_Reserved4_23 "预留4";
CM_ SG_ 2148826968 M2D_CMD1_CRC_24 "CRC校验";
CM_ SG_ 2148826968 M2D_CMD1_DCDCSerialNum_24 "预留  （DCDC编号）";
CM_ SG_ 2148826968 M2D_CMD1_DCDCEnable_24 "使能DCDC命令";
CM_ SG_ 2148826968 M2D_CMD1_Reserved1_24 "预留1";
CM_ SG_ 2148826968 M2D_CMD1_DCDCWrkMdSwtch_24 "DCDC工作状态切换";
CM_ SG_ 2148826968 M2D_CMD1_DCDCWrkMdSet_24 "DCDC工作模式设定";
CM_ SG_ 2148826968 M2D_CMD1_Reserved2_24 "预留2";
CM_ SG_ 2148826968 M2D_CMD1_DCDCOutputCrrntSet_24 "电池电流设定（放正充负）
电池电流=DC低压端电流+DC高压端电流";
CM_ SG_ 2148826968 M2D_CMD1_DCDCOutputVltge_Set_24 "DCDC输出电压设定";
CM_ SG_ 2148826968 M2D_CMD1_Reserved3_24 "预留3";
CM_ SG_ 2148826968 M2D_CMD1_CommunicationState_24 "MBMU与DCDC通讯状态";
CM_ SG_ 2148826968 M2D_CMD1_DCDCFaultClear_24 "DCDC故障清除指令";
CM_ SG_ 2148826968 M2D_CMD1_PCSOperationState_24 "PCS运行状态（预留）";
CM_ SG_ 2148826968 M2D_CMD1_DCDCLVoffControl_24 "DCDC低压下电控制";
CM_ SG_ 2148826968 M2D_CMD1_Reserved4_24 "预留4";
CM_ SG_ 2148826969 M2D_CMD1_CRC_25 "CRC校验";
CM_ SG_ 2148826969 M2D_CMD1_DCDCSerialNum_25 "预留  （DCDC编号）";
CM_ SG_ 2148826969 M2D_CMD1_DCDCEnable_25 "使能DCDC命令";
CM_ SG_ 2148826969 M2D_CMD1_Reserved1_25 "预留1";
CM_ SG_ 2148826969 M2D_CMD1_DCDCWrkMdSwtch_25 "DCDC工作状态切换";
CM_ SG_ 2148826969 M2D_CMD1_DCDCWrkMdSet_25 "DCDC工作模式设定";
CM_ SG_ 2148826969 M2D_CMD1_Reserved2_25 "预留2";
CM_ SG_ 2148826969 M2D_CMD1_DCDCOutputCrrntSet_25 "电池电流设定（放正充负）
电池电流=DC低压端电流+DC高压端电流";
CM_ SG_ 2148826969 M2D_CMD1_DCDCOutputVltge_Set_25 "DCDC输出电压设定";
CM_ SG_ 2148826969 M2D_CMD1_Reserved3_25 "预留3";
CM_ SG_ 2148826969 M2D_CMD1_CommunicationState_25 "MBMU与DCDC通讯状态";
CM_ SG_ 2148826969 M2D_CMD1_DCDCFaultClear_25 "DCDC故障清除指令";
CM_ SG_ 2148826969 M2D_CMD1_PCSOperationState_25 "PCS运行状态（预留）";
CM_ SG_ 2148826969 M2D_CMD1_DCDCLVoffControl_25 "DCDC低压下电控制";
CM_ SG_ 2148826969 M2D_CMD1_Reserved4_25 "预留4";
CM_ SG_ 2148826970 M2D_CMD1_CRC_26 "CRC校验";
CM_ SG_ 2148826970 M2D_CMD1_DCDCSerialNum_26 "预留  （DCDC编号）";
CM_ SG_ 2148826970 M2D_CMD1_DCDCEnable_26 "使能DCDC命令";
CM_ SG_ 2148826970 M2D_CMD1_Reserved1_26 "预留1";
CM_ SG_ 2148826970 M2D_CMD1_DCDCWrkMdSwtch_26 "DCDC工作状态切换";
CM_ SG_ 2148826970 M2D_CMD1_DCDCWrkMdSet_26 "DCDC工作模式设定";
CM_ SG_ 2148826970 M2D_CMD1_Reserved2_26 "预留2";
CM_ SG_ 2148826970 M2D_CMD1_DCDCOutputCrrntSet_26 "电池电流设定（放正充负）
电池电流=DC低压端电流+DC高压端电流";
CM_ SG_ 2148826970 M2D_CMD1_DCDCOutputVltge_Set_26 "DCDC输出电压设定";
CM_ SG_ 2148826970 M2D_CMD1_Reserved3_26 "预留3";
CM_ SG_ 2148826970 M2D_CMD1_CommunicationState_26 "MBMU与DCDC通讯状态";
CM_ SG_ 2148826970 M2D_CMD1_DCDCFaultClear_26 "DCDC故障清除指令";
CM_ SG_ 2148826970 M2D_CMD1_PCSOperationState_26 "PCS运行状态（预留）";
CM_ SG_ 2148826970 M2D_CMD1_DCDCLVoffControl_26 "DCDC低压下电控制";
CM_ SG_ 2148826970 M2D_CMD1_Reserved4_26 "预留4";
CM_ SG_ 2148826971 M2D_CMD1_CRC_27 "CRC校验";
CM_ SG_ 2148826971 M2D_CMD1_DCDCSerialNum_27 "预留  （DCDC编号）";
CM_ SG_ 2148826971 M2D_CMD1_DCDCEnable_27 "使能DCDC命令";
CM_ SG_ 2148826971 M2D_CMD1_Reserved1_27 "预留1";
CM_ SG_ 2148826971 M2D_CMD1_DCDCWrkMdSwtch_27 "DCDC工作状态切换";
CM_ SG_ 2148826971 M2D_CMD1_DCDCWrkMdSet_27 "DCDC工作模式设定";
CM_ SG_ 2148826971 M2D_CMD1_Reserved2_27 "预留2";
CM_ SG_ 2148826971 M2D_CMD1_DCDCOutputCrrntSet_27 "电池电流设定（放正充负）
电池电流=DC低压端电流+DC高压端电流";
CM_ SG_ 2148826971 M2D_CMD1_DCDCOutputVltge_Set_27 "DCDC输出电压设定";
CM_ SG_ 2148826971 M2D_CMD1_Reserved3_27 "预留3";
CM_ SG_ 2148826971 M2D_CMD1_CommunicationState_27 "MBMU与DCDC通讯状态";
CM_ SG_ 2148826971 M2D_CMD1_DCDCFaultClear_27 "DCDC故障清除指令";
CM_ SG_ 2148826971 M2D_CMD1_PCSOperationState_27 "PCS运行状态（预留）";
CM_ SG_ 2148826971 M2D_CMD1_DCDCLVoffControl_27 "DCDC低压下电控制";
CM_ SG_ 2148826971 M2D_CMD1_Reserved4_27 "预留4";
CM_ SG_ 2148826972 M2D_CMD1_CRC_28 "CRC校验";
CM_ SG_ 2148826972 M2D_CMD1_DCDCSerialNum_28 "预留  （DCDC编号）";
CM_ SG_ 2148826972 M2D_CMD1_DCDCEnable_28 "使能DCDC命令";
CM_ SG_ 2148826972 M2D_CMD1_Reserved1_28 "预留1";
CM_ SG_ 2148826972 M2D_CMD1_DCDCWrkMdSwtch_28 "DCDC工作状态切换";
CM_ SG_ 2148826972 M2D_CMD1_DCDCWrkMdSet_28 "DCDC工作模式设定";
CM_ SG_ 2148826972 M2D_CMD1_Reserved2_28 "预留2";
CM_ SG_ 2148826972 M2D_CMD1_DCDCOutputCrrntSet_28 "电池电流设定（放正充负）
电池电流=DC低压端电流+DC高压端电流";
CM_ SG_ 2148826972 M2D_CMD1_DCDCOutputVltge_Set_28 "DCDC输出电压设定";
CM_ SG_ 2148826972 M2D_CMD1_Reserved3_28 "预留3";
CM_ SG_ 2148826972 M2D_CMD1_CommunicationState_28 "MBMU与DCDC通讯状态";
CM_ SG_ 2148826972 M2D_CMD1_DCDCFaultClear_28 "DCDC故障清除指令";
CM_ SG_ 2148826972 M2D_CMD1_PCSOperationState_28 "PCS运行状态（预留）";
CM_ SG_ 2148826972 M2D_CMD1_DCDCLVoffControl_28 "DCDC低压下电控制";
CM_ SG_ 2148826972 M2D_CMD1_Reserved4_28 "预留4";
CM_ SG_ 2148826973 M2D_CMD1_CRC_29 "CRC校验";
CM_ SG_ 2148826973 M2D_CMD1_DCDCSerialNum_29 "预留  （DCDC编号）";
CM_ SG_ 2148826973 M2D_CMD1_DCDCEnable_29 "使能DCDC命令";
CM_ SG_ 2148826973 M2D_CMD1_Reserved1_29 "预留1";
CM_ SG_ 2148826973 M2D_CMD1_DCDCWrkMdSwtch_29 "DCDC工作状态切换";
CM_ SG_ 2148826973 M2D_CMD1_DCDCWrkMdSet_29 "DCDC工作模式设定";
CM_ SG_ 2148826973 M2D_CMD1_Reserved2_29 "预留2";
CM_ SG_ 2148826973 M2D_CMD1_DCDCOutputCrrntSet_29 "电池电流设定（放正充负）
电池电流=DC低压端电流+DC高压端电流";
CM_ SG_ 2148826973 M2D_CMD1_DCDCOutputVltge_Set_29 "DCDC输出电压设定";
CM_ SG_ 2148826973 M2D_CMD1_Reserved3_29 "预留3";
CM_ SG_ 2148826973 M2D_CMD1_CommunicationState_29 "MBMU与DCDC通讯状态";
CM_ SG_ 2148826973 M2D_CMD1_DCDCFaultClear_29 "DCDC故障清除指令";
CM_ SG_ 2148826973 M2D_CMD1_PCSOperationState_29 "PCS运行状态（预留）";
CM_ SG_ 2148826973 M2D_CMD1_DCDCLVoffControl_29 "DCDC低压下电控制";
CM_ SG_ 2148826973 M2D_CMD1_Reserved4_29 "预留4";
CM_ SG_ 2148826974 M2D_CMD1_CRC_30 "CRC校验";
CM_ SG_ 2148826974 M2D_CMD1_DCDCSerialNum_30 "预留  （DCDC编号）";
CM_ SG_ 2148826974 M2D_CMD1_DCDCEnable_30 "使能DCDC命令";
CM_ SG_ 2148826974 M2D_CMD1_Reserved1_30 "预留1";
CM_ SG_ 2148826974 M2D_CMD1_DCDCWrkMdSwtch_30 "DCDC工作状态切换";
CM_ SG_ 2148826974 M2D_CMD1_DCDCWrkMdSet_30 "DCDC工作模式设定";
CM_ SG_ 2148826974 M2D_CMD1_Reserved2_30 "预留2";
CM_ SG_ 2148826974 M2D_CMD1_DCDCOutputCrrntSet_30 "电池电流设定（放正充负）
电池电流=DC低压端电流+DC高压端电流";
CM_ SG_ 2148826974 M2D_CMD1_DCDCOutputVltge_Set_30 "DCDC输出电压设定";
CM_ SG_ 2148826974 M2D_CMD1_Reserved3_30 "预留3";
CM_ SG_ 2148826974 M2D_CMD1_CommunicationState_30 "MBMU与DCDC通讯状态";
CM_ SG_ 2148826974 M2D_CMD1_DCDCFaultClear_30 "DCDC故障清除指令";
CM_ SG_ 2148826974 M2D_CMD1_PCSOperationState_30 "PCS运行状态（预留）";
CM_ SG_ 2148826974 M2D_CMD1_DCDCLVoffControl_30 "DCDC低压下电控制";
CM_ SG_ 2148826974 M2D_CMD1_Reserved4_30 "预留4";
CM_ SG_ 2148826975 M2D_CMD1_CRC_31 "CRC校验";
CM_ SG_ 2148826975 M2D_CMD1_DCDCSerialNum_31 "预留  （DCDC编号）";
CM_ SG_ 2148826975 M2D_CMD1_DCDCEnable_31 "使能DCDC命令";
CM_ SG_ 2148826975 M2D_CMD1_Reserved1_31 "预留1";
CM_ SG_ 2148826975 M2D_CMD1_DCDCWrkMdSwtch_31 "DCDC工作状态切换";
CM_ SG_ 2148826975 M2D_CMD1_DCDCWrkMdSet_31 "DCDC工作模式设定";
CM_ SG_ 2148826975 M2D_CMD1_Reserved2_31 "预留2";
CM_ SG_ 2148826975 M2D_CMD1_DCDCOutputCrrntSet_31 "电池电流设定（放正充负）
电池电流=DC低压端电流+DC高压端电流";
CM_ SG_ 2148826975 M2D_CMD1_DCDCOutputVltge_Set_31 "DCDC输出电压设定";
CM_ SG_ 2148826975 M2D_CMD1_Reserved3_31 "预留3";
CM_ SG_ 2148826975 M2D_CMD1_CommunicationState_31 "MBMU与DCDC通讯状态";
CM_ SG_ 2148826975 M2D_CMD1_DCDCFaultClear_31 "DCDC故障清除指令";
CM_ SG_ 2148826975 M2D_CMD1_PCSOperationState_31 "PCS运行状态（预留）";
CM_ SG_ 2148826975 M2D_CMD1_DCDCLVoffControl_31 "DCDC低压下电控制";
CM_ SG_ 2148826975 M2D_CMD1_Reserved4_31 "预留4";
CM_ SG_ 2148826976 M2D_CMD1_CRC_32 "CRC校验";
CM_ SG_ 2148826976 M2D_CMD1_DCDCSerialNum_32 "预留  （DCDC编号）";
CM_ SG_ 2148826976 M2D_CMD1_DCDCEnable_32 "使能DCDC命令";
CM_ SG_ 2148826976 M2D_CMD1_Reserved1_32 "预留1";
CM_ SG_ 2148826976 M2D_CMD1_DCDCWrkMdSwtch_32 "DCDC工作状态切换";
CM_ SG_ 2148826976 M2D_CMD1_DCDCWrkMdSet_32 "DCDC工作模式设定";
CM_ SG_ 2148826976 M2D_CMD1_Reserved2_32 "预留2";
CM_ SG_ 2148826976 M2D_CMD1_DCDCOutputCrrntSet_32 "电池电流设定（放正充负）
电池电流=DC低压端电流+DC高压端电流";
CM_ SG_ 2148826976 M2D_CMD1_DCDCOutputVltge_Set_32 "DCDC输出电压设定";
CM_ SG_ 2148826976 M2D_CMD1_Reserved3_32 "预留3";
CM_ SG_ 2148826976 M2D_CMD1_CommunicationState_32 "MBMU与DCDC通讯状态";
CM_ SG_ 2148826976 M2D_CMD1_DCDCFaultClear_32 "DCDC故障清除指令";
CM_ SG_ 2148826976 M2D_CMD1_PCSOperationState_32 "PCS运行状态（预留）";
CM_ SG_ 2148826976 M2D_CMD1_DCDCLVoffControl_32 "DCDC低压下电控制";
CM_ SG_ 2148826976 M2D_CMD1_Reserved4_32 "预留4";
CM_ SG_ 2148826977 M2D_CMD1_CRC_33 "CRC校验";
CM_ SG_ 2148826977 M2D_CMD1_DCDCSerialNum_33 "预留  （DCDC编号）";
CM_ SG_ 2148826977 M2D_CMD1_DCDCEnable_33 "使能DCDC命令";
CM_ SG_ 2148826977 M2D_CMD1_Reserved1_33 "预留1";
CM_ SG_ 2148826977 M2D_CMD1_DCDCWrkMdSwtch_33 "DCDC工作状态切换";
CM_ SG_ 2148826977 M2D_CMD1_DCDCWrkMdSet_33 "DCDC工作模式设定";
CM_ SG_ 2148826977 M2D_CMD1_Reserved2_33 "预留2";
CM_ SG_ 2148826977 M2D_CMD1_DCDCOutputCrrntSet_33 "电池电流设定（放正充负）
电池电流=DC低压端电流+DC高压端电流";
CM_ SG_ 2148826977 M2D_CMD1_DCDCOutputVltge_Set_33 "DCDC输出电压设定";
CM_ SG_ 2148826977 M2D_CMD1_Reserved3_33 "预留3";
CM_ SG_ 2148826977 M2D_CMD1_CommunicationState_33 "MBMU与DCDC通讯状态";
CM_ SG_ 2148826977 M2D_CMD1_DCDCFaultClear_33 "DCDC故障清除指令";
CM_ SG_ 2148826977 M2D_CMD1_PCSOperationState_33 "PCS运行状态（预留）";
CM_ SG_ 2148826977 M2D_CMD1_DCDCLVoffControl_33 "DCDC低压下电控制";
CM_ SG_ 2148826977 M2D_CMD1_Reserved4_33 "预留4";
CM_ SG_ 2148826978 M2D_CMD1_CRC_34 "CRC校验";
CM_ SG_ 2148826978 M2D_CMD1_DCDCSerialNum_34 "预留  （DCDC编号）";
CM_ SG_ 2148826978 M2D_CMD1_DCDCEnable_34 "使能DCDC命令";
CM_ SG_ 2148826978 M2D_CMD1_Reserved1_34 "预留1";
CM_ SG_ 2148826978 M2D_CMD1_DCDCWrkMdSwtch_34 "DCDC工作状态切换";
CM_ SG_ 2148826978 M2D_CMD1_DCDCWrkMdSet_34 "DCDC工作模式设定";
CM_ SG_ 2148826978 M2D_CMD1_Reserved2_34 "预留2";
CM_ SG_ 2148826978 M2D_CMD1_DCDCOutputCrrntSet_34 "电池电流设定（放正充负）
电池电流=DC低压端电流+DC高压端电流";
CM_ SG_ 2148826978 M2D_CMD1_DCDCOutputVltge_Set_34 "DCDC输出电压设定";
CM_ SG_ 2148826978 M2D_CMD1_Reserved3_34 "预留3";
CM_ SG_ 2148826978 M2D_CMD1_CommunicationState_34 "MBMU与DCDC通讯状态";
CM_ SG_ 2148826978 M2D_CMD1_DCDCFaultClear_34 "DCDC故障清除指令";
CM_ SG_ 2148826978 M2D_CMD1_PCSOperationState_34 "PCS运行状态（预留）";
CM_ SG_ 2148826978 M2D_CMD1_DCDCLVoffControl_34 "DCDC低压下电控制";
CM_ SG_ 2148826978 M2D_CMD1_Reserved4_34 "预留4";
CM_ SG_ 2148826979 M2D_CMD1_CRC_35 "CRC校验";
CM_ SG_ 2148826979 M2D_CMD1_DCDCSerialNum_35 "预留  （DCDC编号）";
CM_ SG_ 2148826979 M2D_CMD1_DCDCEnable_35 "使能DCDC命令";
CM_ SG_ 2148826979 M2D_CMD1_Reserved1_35 "预留1";
CM_ SG_ 2148826979 M2D_CMD1_DCDCWrkMdSwtch_35 "DCDC工作状态切换";
CM_ SG_ 2148826979 M2D_CMD1_DCDCWrkMdSet_35 "DCDC工作模式设定";
CM_ SG_ 2148826979 M2D_CMD1_Reserved2_35 "预留2";
CM_ SG_ 2148826979 M2D_CMD1_DCDCOutputCrrntSet_35 "电池电流设定（放正充负）
电池电流=DC低压端电流+DC高压端电流";
CM_ SG_ 2148826979 M2D_CMD1_DCDCOutputVltge_Set_35 "DCDC输出电压设定";
CM_ SG_ 2148826979 M2D_CMD1_Reserved3_35 "预留3";
CM_ SG_ 2148826979 M2D_CMD1_CommunicationState_35 "MBMU与DCDC通讯状态";
CM_ SG_ 2148826979 M2D_CMD1_DCDCFaultClear_35 "DCDC故障清除指令";
CM_ SG_ 2148826979 M2D_CMD1_PCSOperationState_35 "PCS运行状态（预留）";
CM_ SG_ 2148826979 M2D_CMD1_DCDCLVoffControl_35 "DCDC低压下电控制";
CM_ SG_ 2148826979 M2D_CMD1_Reserved4_35 "预留4";
CM_ SG_ 2148826980 M2D_CMD1_CRC_36 "CRC校验";
CM_ SG_ 2148826980 M2D_CMD1_DCDCSerialNum_36 "预留  （DCDC编号）";
CM_ SG_ 2148826980 M2D_CMD1_DCDCEnable_36 "使能DCDC命令";
CM_ SG_ 2148826980 M2D_CMD1_Reserved1_36 "预留1";
CM_ SG_ 2148826980 M2D_CMD1_DCDCWrkMdSwtch_36 "DCDC工作状态切换";
CM_ SG_ 2148826980 M2D_CMD1_DCDCWrkMdSet_36 "DCDC工作模式设定";
CM_ SG_ 2148826980 M2D_CMD1_Reserved2_36 "预留2";
CM_ SG_ 2148826980 M2D_CMD1_DCDCOutputCrrntSet_36 "电池电流设定（放正充负）
电池电流=DC低压端电流+DC高压端电流";
CM_ SG_ 2148826980 M2D_CMD1_DCDCOutputVltge_Set_36 "DCDC输出电压设定";
CM_ SG_ 2148826980 M2D_CMD1_Reserved3_36 "预留3";
CM_ SG_ 2148826980 M2D_CMD1_CommunicationState_36 "MBMU与DCDC通讯状态";
CM_ SG_ 2148826980 M2D_CMD1_DCDCFaultClear_36 "DCDC故障清除指令";
CM_ SG_ 2148826980 M2D_CMD1_PCSOperationState_36 "PCS运行状态（预留）";
CM_ SG_ 2148826980 M2D_CMD1_DCDCLVoffControl_36 "DCDC低压下电控制";
CM_ SG_ 2148826980 M2D_CMD1_Reserved4_36 "预留4";
CM_ SG_ 2148826981 M2D_CMD1_CRC_37 "CRC校验";
CM_ SG_ 2148826981 M2D_CMD1_DCDCSerialNum_37 "预留  （DCDC编号）";
CM_ SG_ 2148826981 M2D_CMD1_DCDCEnable_37 "使能DCDC命令";
CM_ SG_ 2148826981 M2D_CMD1_Reserved1_37 "预留1";
CM_ SG_ 2148826981 M2D_CMD1_DCDCWrkMdSwtch_37 "DCDC工作状态切换";
CM_ SG_ 2148826981 M2D_CMD1_DCDCWrkMdSet_37 "DCDC工作模式设定";
CM_ SG_ 2148826981 M2D_CMD1_Reserved2_37 "预留2";
CM_ SG_ 2148826981 M2D_CMD1_DCDCOutputCrrntSet_37 "电池电流设定（放正充负）
电池电流=DC低压端电流+DC高压端电流";
CM_ SG_ 2148826981 M2D_CMD1_DCDCOutputVltge_Set_37 "DCDC输出电压设定";
CM_ SG_ 2148826981 M2D_CMD1_Reserved3_37 "预留3";
CM_ SG_ 2148826981 M2D_CMD1_CommunicationState_37 "MBMU与DCDC通讯状态";
CM_ SG_ 2148826981 M2D_CMD1_DCDCFaultClear_37 "DCDC故障清除指令";
CM_ SG_ 2148826981 M2D_CMD1_PCSOperationState_37 "PCS运行状态（预留）";
CM_ SG_ 2148826981 M2D_CMD1_DCDCLVoffControl_37 "DCDC低压下电控制";
CM_ SG_ 2148826981 M2D_CMD1_Reserved4_37 "预留4";
CM_ SG_ 2148826982 M2D_CMD1_CRC_38 "CRC校验";
CM_ SG_ 2148826982 M2D_CMD1_DCDCSerialNum_38 "预留  （DCDC编号）";
CM_ SG_ 2148826982 M2D_CMD1_DCDCEnable_38 "使能DCDC命令";
CM_ SG_ 2148826982 M2D_CMD1_Reserved1_38 "预留1";
CM_ SG_ 2148826982 M2D_CMD1_DCDCWrkMdSwtch_38 "DCDC工作状态切换";
CM_ SG_ 2148826982 M2D_CMD1_DCDCWrkMdSet_38 "DCDC工作模式设定";
CM_ SG_ 2148826982 M2D_CMD1_Reserved2_38 "预留2";
CM_ SG_ 2148826982 M2D_CMD1_DCDCOutputCrrntSet_38 "电池电流设定（放正充负）
电池电流=DC低压端电流+DC高压端电流";
CM_ SG_ 2148826982 M2D_CMD1_DCDCOutputVltge_Set_38 "DCDC输出电压设定";
CM_ SG_ 2148826982 M2D_CMD1_Reserved3_38 "预留3";
CM_ SG_ 2148826982 M2D_CMD1_CommunicationState_38 "MBMU与DCDC通讯状态";
CM_ SG_ 2148826982 M2D_CMD1_DCDCFaultClear_38 "DCDC故障清除指令";
CM_ SG_ 2148826982 M2D_CMD1_PCSOperationState_38 "PCS运行状态（预留）";
CM_ SG_ 2148826982 M2D_CMD1_DCDCLVoffControl_38 "DCDC低压下电控制";
CM_ SG_ 2148826982 M2D_CMD1_Reserved4_38 "预留4";
CM_ SG_ 2148826983 M2D_CMD1_CRC_39 "CRC校验";
CM_ SG_ 2148826983 M2D_CMD1_DCDCSerialNum_39 "预留  （DCDC编号）";
CM_ SG_ 2148826983 M2D_CMD1_DCDCEnable_39 "使能DCDC命令";
CM_ SG_ 2148826983 M2D_CMD1_Reserved1_39 "预留1";
CM_ SG_ 2148826983 M2D_CMD1_DCDCWrkMdSwtch_39 "DCDC工作状态切换";
CM_ SG_ 2148826983 M2D_CMD1_DCDCWrkMdSet_39 "DCDC工作模式设定";
CM_ SG_ 2148826983 M2D_CMD1_Reserved2_39 "预留2";
CM_ SG_ 2148826983 M2D_CMD1_DCDCOutputCrrntSet_39 "电池电流设定（放正充负）
电池电流=DC低压端电流+DC高压端电流";
CM_ SG_ 2148826983 M2D_CMD1_DCDCOutputVltge_Set_39 "DCDC输出电压设定";
CM_ SG_ 2148826983 M2D_CMD1_Reserved3_39 "预留3";
CM_ SG_ 2148826983 M2D_CMD1_CommunicationState_39 "MBMU与DCDC通讯状态";
CM_ SG_ 2148826983 M2D_CMD1_DCDCFaultClear_39 "DCDC故障清除指令";
CM_ SG_ 2148826983 M2D_CMD1_PCSOperationState_39 "PCS运行状态（预留）";
CM_ SG_ 2148826983 M2D_CMD1_DCDCLVoffControl_39 "DCDC低压下电控制";
CM_ SG_ 2148826983 M2D_CMD1_Reserved4_39 "预留4";
CM_ SG_ 2148826984 M2D_CMD1_CRC_40 "CRC校验";
CM_ SG_ 2148826984 M2D_CMD1_DCDCSerialNum_40 "预留  （DCDC编号）";
CM_ SG_ 2148826984 M2D_CMD1_DCDCEnable_40 "使能DCDC命令";
CM_ SG_ 2148826984 M2D_CMD1_Reserved1_40 "预留1";
CM_ SG_ 2148826984 M2D_CMD1_DCDCWrkMdSwtch_40 "DCDC工作状态切换";
CM_ SG_ 2148826984 M2D_CMD1_DCDCWrkMdSet_40 "DCDC工作模式设定";
CM_ SG_ 2148826984 M2D_CMD1_Reserved2_40 "预留2";
CM_ SG_ 2148826984 M2D_CMD1_DCDCOutputCrrntSet_40 "电池电流设定（放正充负）
电池电流=DC低压端电流+DC高压端电流";
CM_ SG_ 2148826984 M2D_CMD1_DCDCOutputVltge_Set_40 "DCDC输出电压设定";
CM_ SG_ 2148826984 M2D_CMD1_Reserved3_40 "预留3";
CM_ SG_ 2148826984 M2D_CMD1_CommunicationState_40 "MBMU与DCDC通讯状态";
CM_ SG_ 2148826984 M2D_CMD1_DCDCFaultClear_40 "DCDC故障清除指令";
CM_ SG_ 2148826984 M2D_CMD1_PCSOperationState_40 "PCS运行状态（预留）";
CM_ SG_ 2148826984 M2D_CMD1_DCDCLVoffControl_40 "DCDC低压下电控制";
CM_ SG_ 2148826984 M2D_CMD1_Reserved4_40 "预留4";
CM_ SG_ 2148826985 M2D_CMD1_CRC_41 "CRC校验";
CM_ SG_ 2148826985 M2D_CMD1_DCDCSerialNum_41 "预留  （DCDC编号）";
CM_ SG_ 2148826985 M2D_CMD1_DCDCEnable_41 "使能DCDC命令";
CM_ SG_ 2148826985 M2D_CMD1_Reserved1_41 "预留1";
CM_ SG_ 2148826985 M2D_CMD1_DCDCWrkMdSwtch_41 "DCDC工作状态切换";
CM_ SG_ 2148826985 M2D_CMD1_DCDCWrkMdSet_41 "DCDC工作模式设定";
CM_ SG_ 2148826985 M2D_CMD1_Reserved2_41 "预留2";
CM_ SG_ 2148826985 M2D_CMD1_DCDCOutputCrrntSet_41 "电池电流设定（放正充负）
电池电流=DC低压端电流+DC高压端电流";
CM_ SG_ 2148826985 M2D_CMD1_DCDCOutputVltge_Set_41 "DCDC输出电压设定";
CM_ SG_ 2148826985 M2D_CMD1_Reserved3_41 "预留3";
CM_ SG_ 2148826985 M2D_CMD1_CommunicationState_41 "MBMU与DCDC通讯状态";
CM_ SG_ 2148826985 M2D_CMD1_DCDCFaultClear_41 "DCDC故障清除指令";
CM_ SG_ 2148826985 M2D_CMD1_PCSOperationState_41 "PCS运行状态（预留）";
CM_ SG_ 2148826985 M2D_CMD1_DCDCLVoffControl_41 "DCDC低压下电控制";
CM_ SG_ 2148826985 M2D_CMD1_Reserved4_41 "预留4";
CM_ SG_ 2148826986 M2D_CMD1_CRC_42 "CRC校验";
CM_ SG_ 2148826986 M2D_CMD1_DCDCSerialNum_42 "预留  （DCDC编号）";
CM_ SG_ 2148826986 M2D_CMD1_DCDCEnable_42 "使能DCDC命令";
CM_ SG_ 2148826986 M2D_CMD1_Reserved1_42 "预留1";
CM_ SG_ 2148826986 M2D_CMD1_DCDCWrkMdSwtch_42 "DCDC工作状态切换";
CM_ SG_ 2148826986 M2D_CMD1_DCDCWrkMdSet_42 "DCDC工作模式设定";
CM_ SG_ 2148826986 M2D_CMD1_Reserved2_42 "预留2";
CM_ SG_ 2148826986 M2D_CMD1_DCDCOutputCrrntSet_42 "电池电流设定（放正充负）
电池电流=DC低压端电流+DC高压端电流";
CM_ SG_ 2148826986 M2D_CMD1_DCDCOutputVltge_Set_42 "DCDC输出电压设定";
CM_ SG_ 2148826986 M2D_CMD1_Reserved3_42 "预留3";
CM_ SG_ 2148826986 M2D_CMD1_CommunicationState_42 "MBMU与DCDC通讯状态";
CM_ SG_ 2148826986 M2D_CMD1_DCDCFaultClear_42 "DCDC故障清除指令";
CM_ SG_ 2148826986 M2D_CMD1_PCSOperationState_42 "PCS运行状态（预留）";
CM_ SG_ 2148826986 M2D_CMD1_DCDCLVoffControl_42 "DCDC低压下电控制";
CM_ SG_ 2148826986 M2D_CMD1_Reserved4_42 "预留4";
CM_ SG_ 2148826987 M2D_CMD1_CRC_43 "CRC校验";
CM_ SG_ 2148826987 M2D_CMD1_DCDCSerialNum_43 "预留  （DCDC编号）";
CM_ SG_ 2148826987 M2D_CMD1_DCDCEnable_43 "使能DCDC命令";
CM_ SG_ 2148826987 M2D_CMD1_Reserved1_43 "预留1";
CM_ SG_ 2148826987 M2D_CMD1_DCDCWrkMdSwtch_43 "DCDC工作状态切换";
CM_ SG_ 2148826987 M2D_CMD1_DCDCWrkMdSet_43 "DCDC工作模式设定";
CM_ SG_ 2148826987 M2D_CMD1_Reserved2_43 "预留2";
CM_ SG_ 2148826987 M2D_CMD1_DCDCOutputCrrntSet_43 "电池电流设定（放正充负）
电池电流=DC低压端电流+DC高压端电流";
CM_ SG_ 2148826987 M2D_CMD1_DCDCOutputVltge_Set_43 "DCDC输出电压设定";
CM_ SG_ 2148826987 M2D_CMD1_Reserved3_43 "预留3";
CM_ SG_ 2148826987 M2D_CMD1_CommunicationState_43 "MBMU与DCDC通讯状态";
CM_ SG_ 2148826987 M2D_CMD1_DCDCFaultClear_43 "DCDC故障清除指令";
CM_ SG_ 2148826987 M2D_CMD1_PCSOperationState_43 "PCS运行状态（预留）";
CM_ SG_ 2148826987 M2D_CMD1_DCDCLVoffControl_43 "DCDC低压下电控制";
CM_ SG_ 2148826987 M2D_CMD1_Reserved4_43 "预留4";
CM_ SG_ 2148826988 M2D_CMD1_CRC_44 "CRC校验";
CM_ SG_ 2148826988 M2D_CMD1_DCDCSerialNum_44 "预留  （DCDC编号）";
CM_ SG_ 2148826988 M2D_CMD1_DCDCEnable_44 "使能DCDC命令";
CM_ SG_ 2148826988 M2D_CMD1_Reserved1_44 "预留1";
CM_ SG_ 2148826988 M2D_CMD1_DCDCWrkMdSwtch_44 "DCDC工作状态切换";
CM_ SG_ 2148826988 M2D_CMD1_DCDCWrkMdSet_44 "DCDC工作模式设定";
CM_ SG_ 2148826988 M2D_CMD1_Reserved2_44 "预留2";
CM_ SG_ 2148826988 M2D_CMD1_DCDCOutputCrrntSet_44 "电池电流设定（放正充负）
电池电流=DC低压端电流+DC高压端电流";
CM_ SG_ 2148826988 M2D_CMD1_DCDCOutputVltge_Set_44 "DCDC输出电压设定";
CM_ SG_ 2148826988 M2D_CMD1_Reserved3_44 "预留3";
CM_ SG_ 2148826988 M2D_CMD1_CommunicationState_44 "MBMU与DCDC通讯状态";
CM_ SG_ 2148826988 M2D_CMD1_DCDCFaultClear_44 "DCDC故障清除指令";
CM_ SG_ 2148826988 M2D_CMD1_PCSOperationState_44 "PCS运行状态（预留）";
CM_ SG_ 2148826988 M2D_CMD1_DCDCLVoffControl_44 "DCDC低压下电控制";
CM_ SG_ 2148826988 M2D_CMD1_Reserved4_44 "预留4";
CM_ SG_ 2148826989 M2D_CMD1_CRC_45 "CRC校验";
CM_ SG_ 2148826989 M2D_CMD1_DCDCSerialNum_45 "预留  （DCDC编号）";
CM_ SG_ 2148826989 M2D_CMD1_DCDCEnable_45 "使能DCDC命令";
CM_ SG_ 2148826989 M2D_CMD1_Reserved1_45 "预留1";
CM_ SG_ 2148826989 M2D_CMD1_DCDCWrkMdSwtch_45 "DCDC工作状态切换";
CM_ SG_ 2148826989 M2D_CMD1_DCDCWrkMdSet_45 "DCDC工作模式设定";
CM_ SG_ 2148826989 M2D_CMD1_Reserved2_45 "预留2";
CM_ SG_ 2148826989 M2D_CMD1_DCDCOutputCrrntSet_45 "电池电流设定（放正充负）
电池电流=DC低压端电流+DC高压端电流";
CM_ SG_ 2148826989 M2D_CMD1_DCDCOutputVltge_Set_45 "DCDC输出电压设定";
CM_ SG_ 2148826989 M2D_CMD1_Reserved3_45 "预留3";
CM_ SG_ 2148826989 M2D_CMD1_CommunicationState_45 "MBMU与DCDC通讯状态";
CM_ SG_ 2148826989 M2D_CMD1_DCDCFaultClear_45 "DCDC故障清除指令";
CM_ SG_ 2148826989 M2D_CMD1_PCSOperationState_45 "PCS运行状态（预留）";
CM_ SG_ 2148826989 M2D_CMD1_DCDCLVoffControl_45 "DCDC低压下电控制";
CM_ SG_ 2148826989 M2D_CMD1_Reserved4_45 "预留4";
CM_ SG_ 2148826990 M2D_CMD1_CRC_46 "CRC校验";
CM_ SG_ 2148826990 M2D_CMD1_DCDCSerialNum_46 "预留  （DCDC编号）";
CM_ SG_ 2148826990 M2D_CMD1_DCDCEnable_46 "使能DCDC命令";
CM_ SG_ 2148826990 M2D_CMD1_Reserved1_46 "预留1";
CM_ SG_ 2148826990 M2D_CMD1_DCDCWrkMdSwtch_46 "DCDC工作状态切换";
CM_ SG_ 2148826990 M2D_CMD1_DCDCWrkMdSet_46 "DCDC工作模式设定";
CM_ SG_ 2148826990 M2D_CMD1_Reserved2_46 "预留2";
CM_ SG_ 2148826990 M2D_CMD1_DCDCOutputCrrntSet_46 "电池电流设定（放正充负）
电池电流=DC低压端电流+DC高压端电流";
CM_ SG_ 2148826990 M2D_CMD1_DCDCOutputVltge_Set_46 "DCDC输出电压设定";
CM_ SG_ 2148826990 M2D_CMD1_Reserved3_46 "预留3";
CM_ SG_ 2148826990 M2D_CMD1_CommunicationState_46 "MBMU与DCDC通讯状态";
CM_ SG_ 2148826990 M2D_CMD1_DCDCFaultClear_46 "DCDC故障清除指令";
CM_ SG_ 2148826990 M2D_CMD1_PCSOperationState_46 "PCS运行状态（预留）";
CM_ SG_ 2148826990 M2D_CMD1_DCDCLVoffControl_46 "DCDC低压下电控制";
CM_ SG_ 2148826990 M2D_CMD1_Reserved4_46 "预留4";
CM_ SG_ 2148826991 M2D_CMD1_CRC_47 "CRC校验";
CM_ SG_ 2148826991 M2D_CMD1_DCDCSerialNum_47 "预留  （DCDC编号）";
CM_ SG_ 2148826991 M2D_CMD1_DCDCEnable_47 "使能DCDC命令";
CM_ SG_ 2148826991 M2D_CMD1_Reserved1_47 "预留1";
CM_ SG_ 2148826991 M2D_CMD1_DCDCWrkMdSwtch_47 "DCDC工作状态切换";
CM_ SG_ 2148826991 M2D_CMD1_DCDCWrkMdSet_47 "DCDC工作模式设定";
CM_ SG_ 2148826991 M2D_CMD1_Reserved2_47 "预留2";
CM_ SG_ 2148826991 M2D_CMD1_DCDCOutputCrrntSet_47 "电池电流设定（放正充负）
电池电流=DC低压端电流+DC高压端电流";
CM_ SG_ 2148826991 M2D_CMD1_DCDCOutputVltge_Set_47 "DCDC输出电压设定";
CM_ SG_ 2148826991 M2D_CMD1_Reserved3_47 "预留3";
CM_ SG_ 2148826991 M2D_CMD1_CommunicationState_47 "MBMU与DCDC通讯状态";
CM_ SG_ 2148826991 M2D_CMD1_DCDCFaultClear_47 "DCDC故障清除指令";
CM_ SG_ 2148826991 M2D_CMD1_PCSOperationState_47 "PCS运行状态（预留）";
CM_ SG_ 2148826991 M2D_CMD1_DCDCLVoffControl_47 "DCDC低压下电控制";
CM_ SG_ 2148826991 M2D_CMD1_Reserved4_47 "预留4";
CM_ SG_ 2148826992 M2D_CMD1_CRC_48 "CRC校验";
CM_ SG_ 2148826992 M2D_CMD1_DCDCSerialNum_48 "预留  （DCDC编号）";
CM_ SG_ 2148826992 M2D_CMD1_DCDCEnable_48 "使能DCDC命令";
CM_ SG_ 2148826992 M2D_CMD1_Reserved1_48 "预留1";
CM_ SG_ 2148826992 M2D_CMD1_DCDCWrkMdSwtch_48 "DCDC工作状态切换";
CM_ SG_ 2148826992 M2D_CMD1_DCDCWrkMdSet_48 "DCDC工作模式设定";
CM_ SG_ 2148826992 M2D_CMD1_Reserved2_48 "预留2";
CM_ SG_ 2148826992 M2D_CMD1_DCDCOutputCrrntSet_48 "电池电流设定（放正充负）
电池电流=DC低压端电流+DC高压端电流";
CM_ SG_ 2148826992 M2D_CMD1_DCDCOutputVltge_Set_48 "DCDC输出电压设定";
CM_ SG_ 2148826992 M2D_CMD1_Reserved3_48 "预留3";
CM_ SG_ 2148826992 M2D_CMD1_CommunicationState_48 "MBMU与DCDC通讯状态";
CM_ SG_ 2148826992 M2D_CMD1_DCDCFaultClear_48 "DCDC故障清除指令";
CM_ SG_ 2148826992 M2D_CMD1_PCSOperationState_48 "PCS运行状态（预留）";
CM_ SG_ 2148826992 M2D_CMD1_DCDCLVoffControl_48 "DCDC低压下电控制";
CM_ SG_ 2148826992 M2D_CMD1_Reserved4_48 "预留4";
CM_ SG_ 2148826993 M2D_CMD1_CRC_49 "CRC校验";
CM_ SG_ 2148826993 M2D_CMD1_DCDCSerialNum_49 "预留  （DCDC编号）";
CM_ SG_ 2148826993 M2D_CMD1_DCDCEnable_49 "使能DCDC命令";
CM_ SG_ 2148826993 M2D_CMD1_Reserved1_49 "预留1";
CM_ SG_ 2148826993 M2D_CMD1_DCDCWrkMdSwtch_49 "DCDC工作状态切换";
CM_ SG_ 2148826993 M2D_CMD1_DCDCWrkMdSet_49 "DCDC工作模式设定";
CM_ SG_ 2148826993 M2D_CMD1_Reserved2_49 "预留2";
CM_ SG_ 2148826993 M2D_CMD1_DCDCOutputCrrntSet_49 "电池电流设定（放正充负）
电池电流=DC低压端电流+DC高压端电流";
CM_ SG_ 2148826993 M2D_CMD1_DCDCOutputVltge_Set_49 "DCDC输出电压设定";
CM_ SG_ 2148826993 M2D_CMD1_Reserved3_49 "预留3";
CM_ SG_ 2148826993 M2D_CMD1_CommunicationState_49 "MBMU与DCDC通讯状态";
CM_ SG_ 2148826993 M2D_CMD1_DCDCFaultClear_49 "DCDC故障清除指令";
CM_ SG_ 2148826993 M2D_CMD1_PCSOperationState_49 "PCS运行状态（预留）";
CM_ SG_ 2148826993 M2D_CMD1_DCDCLVoffControl_49 "DCDC低压下电控制";
CM_ SG_ 2148826993 M2D_CMD1_Reserved4_49 "预留4";
CM_ SG_ 2148826994 M2D_CMD1_CRC_50 "CRC校验";
CM_ SG_ 2148826994 M2D_CMD1_DCDCSerialNum_50 "预留  （DCDC编号）";
CM_ SG_ 2148826994 M2D_CMD1_DCDCEnable_50 "使能DCDC命令";
CM_ SG_ 2148826994 M2D_CMD1_Reserved1_50 "预留1";
CM_ SG_ 2148826994 M2D_CMD1_DCDCWrkMdSwtch_50 "DCDC工作状态切换";
CM_ SG_ 2148826994 M2D_CMD1_DCDCWrkMdSet_50 "DCDC工作模式设定";
CM_ SG_ 2148826994 M2D_CMD1_Reserved2_50 "预留2";
CM_ SG_ 2148826994 M2D_CMD1_DCDCOutputCrrntSet_50 "电池电流设定（放正充负）
电池电流=DC低压端电流+DC高压端电流";
CM_ SG_ 2148826994 M2D_CMD1_DCDCOutputVltge_Set_50 "DCDC输出电压设定";
CM_ SG_ 2148826994 M2D_CMD1_Reserved3_50 "预留3";
CM_ SG_ 2148826994 M2D_CMD1_CommunicationState_50 "MBMU与DCDC通讯状态";
CM_ SG_ 2148826994 M2D_CMD1_DCDCFaultClear_50 "DCDC故障清除指令";
CM_ SG_ 2148826994 M2D_CMD1_PCSOperationState_50 "PCS运行状态（预留）";
CM_ SG_ 2148826994 M2D_CMD1_DCDCLVoffControl_50 "DCDC低压下电控制";
CM_ SG_ 2148826994 M2D_CMD1_Reserved4_50 "预留4";
CM_ SG_ 2148826995 M2D_CMD1_CRC_51 "CRC校验";
CM_ SG_ 2148826995 M2D_CMD1_DCDCSerialNum_51 "预留  （DCDC编号）";
CM_ SG_ 2148826995 M2D_CMD1_DCDCEnable_51 "使能DCDC命令";
CM_ SG_ 2148826995 M2D_CMD1_Reserved1_51 "预留1";
CM_ SG_ 2148826995 M2D_CMD1_DCDCWrkMdSwtch_51 "DCDC工作状态切换";
CM_ SG_ 2148826995 M2D_CMD1_DCDCWrkMdSet_51 "DCDC工作模式设定";
CM_ SG_ 2148826995 M2D_CMD1_Reserved2_51 "预留2";
CM_ SG_ 2148826995 M2D_CMD1_DCDCOutputCrrntSet_51 "电池电流设定（放正充负）
电池电流=DC低压端电流+DC高压端电流";
CM_ SG_ 2148826995 M2D_CMD1_DCDCOutputVltge_Set_51 "DCDC输出电压设定";
CM_ SG_ 2148826995 M2D_CMD1_Reserved3_51 "预留3";
CM_ SG_ 2148826995 M2D_CMD1_CommunicationState_51 "MBMU与DCDC通讯状态";
CM_ SG_ 2148826995 M2D_CMD1_DCDCFaultClear_51 "DCDC故障清除指令";
CM_ SG_ 2148826995 M2D_CMD1_PCSOperationState_51 "PCS运行状态（预留）";
CM_ SG_ 2148826995 M2D_CMD1_DCDCLVoffControl_51 "DCDC低压下电控制";
CM_ SG_ 2148826995 M2D_CMD1_Reserved4_51 "预留4";
CM_ SG_ 2148826996 M2D_CMD1_CRC_52 "CRC校验";
CM_ SG_ 2148826996 M2D_CMD1_DCDCSerialNum_52 "预留  （DCDC编号）";
CM_ SG_ 2148826996 M2D_CMD1_DCDCEnable_52 "使能DCDC命令";
CM_ SG_ 2148826996 M2D_CMD1_Reserved1_52 "预留1";
CM_ SG_ 2148826996 M2D_CMD1_DCDCWrkMdSwtch_52 "DCDC工作状态切换";
CM_ SG_ 2148826996 M2D_CMD1_DCDCWrkMdSet_52 "DCDC工作模式设定";
CM_ SG_ 2148826996 M2D_CMD1_Reserved2_52 "预留2";
CM_ SG_ 2148826996 M2D_CMD1_DCDCOutputCrrntSet_52 "电池电流设定（放正充负）
电池电流=DC低压端电流+DC高压端电流";
CM_ SG_ 2148826996 M2D_CMD1_DCDCOutputVltge_Set_52 "DCDC输出电压设定";
CM_ SG_ 2148826996 M2D_CMD1_Reserved3_52 "预留3";
CM_ SG_ 2148826996 M2D_CMD1_CommunicationState_52 "MBMU与DCDC通讯状态";
CM_ SG_ 2148826996 M2D_CMD1_DCDCFaultClear_52 "DCDC故障清除指令";
CM_ SG_ 2148826996 M2D_CMD1_PCSOperationState_52 "PCS运行状态（预留）";
CM_ SG_ 2148826996 M2D_CMD1_DCDCLVoffControl_52 "DCDC低压下电控制";
CM_ SG_ 2148826996 M2D_CMD1_Reserved4_52 "预留4";
CM_ SG_ 2148826997 M2D_CMD1_CRC_53 "CRC校验";
CM_ SG_ 2148826997 M2D_CMD1_DCDCSerialNum_53 "预留  （DCDC编号）";
CM_ SG_ 2148826997 M2D_CMD1_DCDCEnable_53 "使能DCDC命令";
CM_ SG_ 2148826997 M2D_CMD1_Reserved1_53 "预留1";
CM_ SG_ 2148826997 M2D_CMD1_DCDCWrkMdSwtch_53 "DCDC工作状态切换";
CM_ SG_ 2148826997 M2D_CMD1_DCDCWrkMdSet_53 "DCDC工作模式设定";
CM_ SG_ 2148826997 M2D_CMD1_Reserved2_53 "预留2";
CM_ SG_ 2148826997 M2D_CMD1_DCDCOutputCrrntSet_53 "电池电流设定（放正充负）
电池电流=DC低压端电流+DC高压端电流";
CM_ SG_ 2148826997 M2D_CMD1_DCDCOutputVltge_Set_53 "DCDC输出电压设定";
CM_ SG_ 2148826997 M2D_CMD1_Reserved3_53 "预留3";
CM_ SG_ 2148826997 M2D_CMD1_CommunicationState_53 "MBMU与DCDC通讯状态";
CM_ SG_ 2148826997 M2D_CMD1_DCDCFaultClear_53 "DCDC故障清除指令";
CM_ SG_ 2148826997 M2D_CMD1_PCSOperationState_53 "PCS运行状态（预留）";
CM_ SG_ 2148826997 M2D_CMD1_DCDCLVoffControl_53 "DCDC低压下电控制";
CM_ SG_ 2148826997 M2D_CMD1_Reserved4_53 "预留4";
CM_ SG_ 2148826998 M2D_CMD1_CRC_54 "CRC校验";
CM_ SG_ 2148826998 M2D_CMD1_DCDCSerialNum_54 "预留  （DCDC编号）";
CM_ SG_ 2148826998 M2D_CMD1_DCDCEnable_54 "使能DCDC命令";
CM_ SG_ 2148826998 M2D_CMD1_Reserved1_54 "预留1";
CM_ SG_ 2148826998 M2D_CMD1_DCDCWrkMdSwtch_54 "DCDC工作状态切换";
CM_ SG_ 2148826998 M2D_CMD1_DCDCWrkMdSet_54 "DCDC工作模式设定";
CM_ SG_ 2148826998 M2D_CMD1_Reserved2_54 "预留2";
CM_ SG_ 2148826998 M2D_CMD1_DCDCOutputCrrntSet_54 "电池电流设定（放正充负）
电池电流=DC低压端电流+DC高压端电流";
CM_ SG_ 2148826998 M2D_CMD1_DCDCOutputVltge_Set_54 "DCDC输出电压设定";
CM_ SG_ 2148826998 M2D_CMD1_Reserved3_54 "预留3";
CM_ SG_ 2148826998 M2D_CMD1_CommunicationState_54 "MBMU与DCDC通讯状态";
CM_ SG_ 2148826998 M2D_CMD1_DCDCFaultClear_54 "DCDC故障清除指令";
CM_ SG_ 2148826998 M2D_CMD1_PCSOperationState_54 "PCS运行状态（预留）";
CM_ SG_ 2148826998 M2D_CMD1_DCDCLVoffControl_54 "DCDC低压下电控制";
CM_ SG_ 2148826998 M2D_CMD1_Reserved4_54 "预留4";
CM_ SG_ 2148826999 M2D_CMD1_CRC_55 "CRC校验";
CM_ SG_ 2148826999 M2D_CMD1_DCDCSerialNum_55 "预留  （DCDC编号）";
CM_ SG_ 2148826999 M2D_CMD1_DCDCEnable_55 "使能DCDC命令";
CM_ SG_ 2148826999 M2D_CMD1_Reserved1_55 "预留1";
CM_ SG_ 2148826999 M2D_CMD1_DCDCWrkMdSwtch_55 "DCDC工作状态切换";
CM_ SG_ 2148826999 M2D_CMD1_DCDCWrkMdSet_55 "DCDC工作模式设定";
CM_ SG_ 2148826999 M2D_CMD1_Reserved2_55 "预留2";
CM_ SG_ 2148826999 M2D_CMD1_DCDCOutputCrrntSet_55 "电池电流设定（放正充负）
电池电流=DC低压端电流+DC高压端电流";
CM_ SG_ 2148826999 M2D_CMD1_DCDCOutputVltge_Set_55 "DCDC输出电压设定";
CM_ SG_ 2148826999 M2D_CMD1_Reserved3_55 "预留3";
CM_ SG_ 2148826999 M2D_CMD1_CommunicationState_55 "MBMU与DCDC通讯状态";
CM_ SG_ 2148826999 M2D_CMD1_DCDCFaultClear_55 "DCDC故障清除指令";
CM_ SG_ 2148826999 M2D_CMD1_PCSOperationState_55 "PCS运行状态（预留）";
CM_ SG_ 2148826999 M2D_CMD1_DCDCLVoffControl_55 "DCDC低压下电控制";
CM_ SG_ 2148826999 M2D_CMD1_Reserved4_55 "预留4";
CM_ SG_ 2148827000 M2D_CMD1_CRC_56 "CRC校验";
CM_ SG_ 2148827000 M2D_CMD1_DCDCSerialNum_56 "预留  （DCDC编号）";
CM_ SG_ 2148827000 M2D_CMD1_DCDCEnable_56 "使能DCDC命令";
CM_ SG_ 2148827000 M2D_CMD1_Reserved1_56 "预留1";
CM_ SG_ 2148827000 M2D_CMD1_DCDCWrkMdSwtch_56 "DCDC工作状态切换";
CM_ SG_ 2148827000 M2D_CMD1_DCDCWrkMdSet_56 "DCDC工作模式设定";
CM_ SG_ 2148827000 M2D_CMD1_Reserved2_56 "预留2";
CM_ SG_ 2148827000 M2D_CMD1_DCDCOutputCrrntSet_56 "电池电流设定（放正充负）
电池电流=DC低压端电流+DC高压端电流";
CM_ SG_ 2148827000 M2D_CMD1_DCDCOutputVltge_Set_56 "DCDC输出电压设定";
CM_ SG_ 2148827000 M2D_CMD1_Reserved3_56 "预留3";
CM_ SG_ 2148827000 M2D_CMD1_CommunicationState_56 "MBMU与DCDC通讯状态";
CM_ SG_ 2148827000 M2D_CMD1_DCDCFaultClear_56 "DCDC故障清除指令";
CM_ SG_ 2148827000 M2D_CMD1_PCSOperationState_56 "PCS运行状态（预留）";
CM_ SG_ 2148827000 M2D_CMD1_DCDCLVoffControl_56 "DCDC低压下电控制";
CM_ SG_ 2148827000 M2D_CMD1_Reserved4_56 "预留4";
CM_ SG_ 2148827001 M2D_CMD1_CRC_57 "CRC校验";
CM_ SG_ 2148827001 M2D_CMD1_DCDCSerialNum_57 "预留  （DCDC编号）";
CM_ SG_ 2148827001 M2D_CMD1_DCDCEnable_57 "使能DCDC命令";
CM_ SG_ 2148827001 M2D_CMD1_Reserved1_57 "预留1";
CM_ SG_ 2148827001 M2D_CMD1_DCDCWrkMdSwtch_57 "DCDC工作状态切换";
CM_ SG_ 2148827001 M2D_CMD1_DCDCWrkMdSet_57 "DCDC工作模式设定";
CM_ SG_ 2148827001 M2D_CMD1_Reserved2_57 "预留2";
CM_ SG_ 2148827001 M2D_CMD1_DCDCOutputCrrntSet_57 "电池电流设定（放正充负）
电池电流=DC低压端电流+DC高压端电流";
CM_ SG_ 2148827001 M2D_CMD1_DCDCOutputVltge_Set_57 "DCDC输出电压设定";
CM_ SG_ 2148827001 M2D_CMD1_Reserved3_57 "预留3";
CM_ SG_ 2148827001 M2D_CMD1_CommunicationState_57 "MBMU与DCDC通讯状态";
CM_ SG_ 2148827001 M2D_CMD1_DCDCFaultClear_57 "DCDC故障清除指令";
CM_ SG_ 2148827001 M2D_CMD1_PCSOperationState_57 "PCS运行状态（预留）";
CM_ SG_ 2148827001 M2D_CMD1_DCDCLVoffControl_57 "DCDC低压下电控制";
CM_ SG_ 2148827001 M2D_CMD1_Reserved4_57 "预留4";
CM_ SG_ 2148827002 M2D_CMD1_CRC_58 "CRC校验";
CM_ SG_ 2148827002 M2D_CMD1_DCDCSerialNum_58 "预留  （DCDC编号）";
CM_ SG_ 2148827002 M2D_CMD1_DCDCEnable_58 "使能DCDC命令";
CM_ SG_ 2148827002 M2D_CMD1_Reserved1_58 "预留1";
CM_ SG_ 2148827002 M2D_CMD1_DCDCWrkMdSwtch_58 "DCDC工作状态切换";
CM_ SG_ 2148827002 M2D_CMD1_DCDCWrkMdSet_58 "DCDC工作模式设定";
CM_ SG_ 2148827002 M2D_CMD1_Reserved2_58 "预留2";
CM_ SG_ 2148827002 M2D_CMD1_DCDCOutputCrrntSet_58 "电池电流设定（放正充负）
电池电流=DC低压端电流+DC高压端电流";
CM_ SG_ 2148827002 M2D_CMD1_DCDCOutputVltge_Set_58 "DCDC输出电压设定";
CM_ SG_ 2148827002 M2D_CMD1_Reserved3_58 "预留3";
CM_ SG_ 2148827002 M2D_CMD1_CommunicationState_58 "MBMU与DCDC通讯状态";
CM_ SG_ 2148827002 M2D_CMD1_DCDCFaultClear_58 "DCDC故障清除指令";
CM_ SG_ 2148827002 M2D_CMD1_PCSOperationState_58 "PCS运行状态（预留）";
CM_ SG_ 2148827002 M2D_CMD1_DCDCLVoffControl_58 "DCDC低压下电控制";
CM_ SG_ 2148827002 M2D_CMD1_Reserved4_58 "预留4";
CM_ SG_ 2148827003 M2D_CMD1_CRC_59 "CRC校验";
CM_ SG_ 2148827003 M2D_CMD1_DCDCSerialNum_59 "预留  （DCDC编号）";
CM_ SG_ 2148827003 M2D_CMD1_DCDCEnable_59 "使能DCDC命令";
CM_ SG_ 2148827003 M2D_CMD1_Reserved1_59 "预留1";
CM_ SG_ 2148827003 M2D_CMD1_DCDCWrkMdSwtch_59 "DCDC工作状态切换";
CM_ SG_ 2148827003 M2D_CMD1_DCDCWrkMdSet_59 "DCDC工作模式设定";
CM_ SG_ 2148827003 M2D_CMD1_Reserved2_59 "预留2";
CM_ SG_ 2148827003 M2D_CMD1_DCDCOutputCrrntSet_59 "电池电流设定（放正充负）
电池电流=DC低压端电流+DC高压端电流";
CM_ SG_ 2148827003 M2D_CMD1_DCDCOutputVltge_Set_59 "DCDC输出电压设定";
CM_ SG_ 2148827003 M2D_CMD1_Reserved3_59 "预留3";
CM_ SG_ 2148827003 M2D_CMD1_CommunicationState_59 "MBMU与DCDC通讯状态";
CM_ SG_ 2148827003 M2D_CMD1_DCDCFaultClear_59 "DCDC故障清除指令";
CM_ SG_ 2148827003 M2D_CMD1_PCSOperationState_59 "PCS运行状态（预留）";
CM_ SG_ 2148827003 M2D_CMD1_DCDCLVoffControl_59 "DCDC低压下电控制";
CM_ SG_ 2148827003 M2D_CMD1_Reserved4_59 "预留4";
CM_ SG_ 2148827004 M2D_CMD1_CRC_60 "CRC校验";
CM_ SG_ 2148827004 M2D_CMD1_DCDCSerialNum_60 "预留  （DCDC编号）";
CM_ SG_ 2148827004 M2D_CMD1_DCDCEnable_60 "使能DCDC命令";
CM_ SG_ 2148827004 M2D_CMD1_Reserved1_60 "预留1";
CM_ SG_ 2148827004 M2D_CMD1_DCDCWrkMdSwtch_60 "DCDC工作状态切换";
CM_ SG_ 2148827004 M2D_CMD1_DCDCWrkMdSet_60 "DCDC工作模式设定";
CM_ SG_ 2148827004 M2D_CMD1_Reserved2_60 "预留2";
CM_ SG_ 2148827004 M2D_CMD1_DCDCOutputCrrntSet_60 "电池电流设定（放正充负）
电池电流=DC低压端电流+DC高压端电流";
CM_ SG_ 2148827004 M2D_CMD1_DCDCOutputVltge_Set_60 "DCDC输出电压设定";
CM_ SG_ 2148827004 M2D_CMD1_Reserved3_60 "预留3";
CM_ SG_ 2148827004 M2D_CMD1_CommunicationState_60 "MBMU与DCDC通讯状态";
CM_ SG_ 2148827004 M2D_CMD1_DCDCFaultClear_60 "DCDC故障清除指令";
CM_ SG_ 2148827004 M2D_CMD1_PCSOperationState_60 "PCS运行状态（预留）";
CM_ SG_ 2148827004 M2D_CMD1_DCDCLVoffControl_60 "DCDC低压下电控制";
CM_ SG_ 2148827004 M2D_CMD1_Reserved4_60 "预留4";
CM_ SG_ 2148827005 M2D_CMD1_CRC_61 "CRC校验";
CM_ SG_ 2148827005 M2D_CMD1_DCDCSerialNum_61 "预留  （DCDC编号）";
CM_ SG_ 2148827005 M2D_CMD1_DCDCEnable_61 "使能DCDC命令";
CM_ SG_ 2148827005 M2D_CMD1_Reserved1_61 "预留1";
CM_ SG_ 2148827005 M2D_CMD1_DCDCWrkMdSwtch_61 "DCDC工作状态切换";
CM_ SG_ 2148827005 M2D_CMD1_DCDCWrkMdSet_61 "DCDC工作模式设定";
CM_ SG_ 2148827005 M2D_CMD1_Reserved2_61 "预留2";
CM_ SG_ 2148827005 M2D_CMD1_DCDCOutputCrrntSet_61 "电池电流设定（放正充负）
电池电流=DC低压端电流+DC高压端电流";
CM_ SG_ 2148827005 M2D_CMD1_DCDCOutputVltge_Set_61 "DCDC输出电压设定";
CM_ SG_ 2148827005 M2D_CMD1_Reserved3_61 "预留3";
CM_ SG_ 2148827005 M2D_CMD1_CommunicationState_61 "MBMU与DCDC通讯状态";
CM_ SG_ 2148827005 M2D_CMD1_DCDCFaultClear_61 "DCDC故障清除指令";
CM_ SG_ 2148827005 M2D_CMD1_PCSOperationState_61 "PCS运行状态（预留）";
CM_ SG_ 2148827005 M2D_CMD1_DCDCLVoffControl_61 "DCDC低压下电控制";
CM_ SG_ 2148827005 M2D_CMD1_Reserved4_61 "预留4";
CM_ SG_ 2148827006 M2D_CMD1_CRC_62 "CRC校验";
CM_ SG_ 2148827006 M2D_CMD1_DCDCSerialNum_62 "预留  （DCDC编号）";
CM_ SG_ 2148827006 M2D_CMD1_DCDCEnable_62 "使能DCDC命令";
CM_ SG_ 2148827006 M2D_CMD1_Reserved1_62 "预留1";
CM_ SG_ 2148827006 M2D_CMD1_DCDCWrkMdSwtch_62 "DCDC工作状态切换";
CM_ SG_ 2148827006 M2D_CMD1_DCDCWrkMdSet_62 "DCDC工作模式设定";
CM_ SG_ 2148827006 M2D_CMD1_Reserved2_62 "预留2";
CM_ SG_ 2148827006 M2D_CMD1_DCDCOutputCrrntSet_62 "电池电流设定（放正充负）
电池电流=DC低压端电流+DC高压端电流";
CM_ SG_ 2148827006 M2D_CMD1_DCDCOutputVltge_Set_62 "DCDC输出电压设定";
CM_ SG_ 2148827006 M2D_CMD1_Reserved3_62 "预留3";
CM_ SG_ 2148827006 M2D_CMD1_CommunicationState_62 "MBMU与DCDC通讯状态";
CM_ SG_ 2148827006 M2D_CMD1_DCDCFaultClear_62 "DCDC故障清除指令";
CM_ SG_ 2148827006 M2D_CMD1_PCSOperationState_62 "PCS运行状态（预留）";
CM_ SG_ 2148827006 M2D_CMD1_DCDCLVoffControl_62 "DCDC低压下电控制";
CM_ SG_ 2148827006 M2D_CMD1_Reserved4_62 "预留4";
CM_ SG_ 2148827007 M2D_CMD1_CRC_63 "CRC校验";
CM_ SG_ 2148827007 M2D_CMD1_DCDCSerialNum_63 "预留  （DCDC编号）";
CM_ SG_ 2148827007 M2D_CMD1_DCDCEnable_63 "使能DCDC命令";
CM_ SG_ 2148827007 M2D_CMD1_Reserved1_63 "预留1";
CM_ SG_ 2148827007 M2D_CMD1_DCDCWrkMdSwtch_63 "DCDC工作状态切换";
CM_ SG_ 2148827007 M2D_CMD1_DCDCWrkMdSet_63 "DCDC工作模式设定";
CM_ SG_ 2148827007 M2D_CMD1_Reserved2_63 "预留2";
CM_ SG_ 2148827007 M2D_CMD1_DCDCOutputCrrntSet_63 "电池电流设定（放正充负）
电池电流=DC低压端电流+DC高压端电流";
CM_ SG_ 2148827007 M2D_CMD1_DCDCOutputVltge_Set_63 "DCDC输出电压设定";
CM_ SG_ 2148827007 M2D_CMD1_Reserved3_63 "预留3";
CM_ SG_ 2148827007 M2D_CMD1_CommunicationState_63 "MBMU与DCDC通讯状态";
CM_ SG_ 2148827007 M2D_CMD1_DCDCFaultClear_63 "DCDC故障清除指令";
CM_ SG_ 2148827007 M2D_CMD1_PCSOperationState_63 "PCS运行状态（预留）";
CM_ SG_ 2148827007 M2D_CMD1_DCDCLVoffControl_63 "DCDC低压下电控制";
CM_ SG_ 2148827007 M2D_CMD1_Reserved4_63 "预留4";
CM_ SG_ 2148892481 M2D_CMD2_CRC_01 "CRC校验";
CM_ SG_ 2148892481 M2D_IDX_CMD_Type_01 "MBMU发送给DCDC的自动编码命令类型";
CM_ SG_ 2148892481 M2D_IDX_DCDC_Index_01 "MBMU发送给DCDC的DCDC的编码地址";
CM_ SG_ 2148892481 M2D_IDX_DCDC_Matchingcode_01 "MBMU发送给DCDC的DCDC的匹配码";
CM_ SG_ 2148892481 M2D_IDX_Reserved_01 "预留";
CM_ SG_ 2148892482 M2D_CMD2_CRC_02 "CRC校验";
CM_ SG_ 2148892482 M2D_IDX_CMD_Type_02 "MBMU发送给DCDC的自动编码命令类型";
CM_ SG_ 2148892482 M2D_IDX_DCDC_Index_02 "MBMU发送给DCDC的DCDC的编码地址";
CM_ SG_ 2148892482 M2D_IDX_DCDC_Matchingcode_02 "MBMU发送给DCDC的DCDC的匹配码";
CM_ SG_ 2148892482 M2D_IDX_Reserved_02 "预留";
CM_ SG_ 2148892483 M2D_CMD2_CRC_03 "CRC校验";
CM_ SG_ 2148892483 M2D_IDX_CMD_Type_03 "MBMU发送给DCDC的自动编码命令类型";
CM_ SG_ 2148892483 M2D_IDX_DCDC_Index_03 "MBMU发送给DCDC的DCDC的编码地址";
CM_ SG_ 2148892483 M2D_IDX_DCDC_Matchingcode_03 "MBMU发送给DCDC的DCDC的匹配码";
CM_ SG_ 2148892483 M2D_IDX_Reserved_03 "预留";
CM_ SG_ 2148892484 M2D_CMD2_CRC_04 "CRC校验";
CM_ SG_ 2148892484 M2D_IDX_CMD_Type_04 "MBMU发送给DCDC的自动编码命令类型";
CM_ SG_ 2148892484 M2D_IDX_DCDC_Index_04 "MBMU发送给DCDC的DCDC的编码地址";
CM_ SG_ 2148892484 M2D_IDX_DCDC_Matchingcode_04 "MBMU发送给DCDC的DCDC的匹配码";
CM_ SG_ 2148892484 M2D_IDX_Reserved_04 "预留";
CM_ SG_ 2148892485 M2D_CMD2_CRC_05 "CRC校验";
CM_ SG_ 2148892485 M2D_IDX_CMD_Type_05 "MBMU发送给DCDC的自动编码命令类型";
CM_ SG_ 2148892485 M2D_IDX_DCDC_Index_05 "MBMU发送给DCDC的DCDC的编码地址";
CM_ SG_ 2148892485 M2D_IDX_DCDC_Matchingcode_05 "MBMU发送给DCDC的DCDC的匹配码";
CM_ SG_ 2148892485 M2D_IDX_Reserved_05 "预留";
CM_ SG_ 2148892486 M2D_CMD2_CRC_06 "CRC校验";
CM_ SG_ 2148892486 M2D_IDX_CMD_Type_06 "MBMU发送给DCDC的自动编码命令类型";
CM_ SG_ 2148892486 M2D_IDX_DCDC_Index_06 "MBMU发送给DCDC的DCDC的编码地址";
CM_ SG_ 2148892486 M2D_IDX_DCDC_Matchingcode_06 "MBMU发送给DCDC的DCDC的匹配码";
CM_ SG_ 2148892486 M2D_IDX_Reserved_06 "预留";
CM_ SG_ 2148892487 M2D_CMD2_CRC_07 "CRC校验";
CM_ SG_ 2148892487 M2D_IDX_CMD_Type_07 "MBMU发送给DCDC的自动编码命令类型";
CM_ SG_ 2148892487 M2D_IDX_DCDC_Index_07 "MBMU发送给DCDC的DCDC的编码地址";
CM_ SG_ 2148892487 M2D_IDX_DCDC_Matchingcode_07 "MBMU发送给DCDC的DCDC的匹配码";
CM_ SG_ 2148892487 M2D_IDX_Reserved_07 "预留";
CM_ SG_ 2148892488 M2D_CMD2_CRC_08 "CRC校验";
CM_ SG_ 2148892488 M2D_IDX_CMD_Type_08 "MBMU发送给DCDC的自动编码命令类型";
CM_ SG_ 2148892488 M2D_IDX_DCDC_Index_08 "MBMU发送给DCDC的DCDC的编码地址";
CM_ SG_ 2148892488 M2D_IDX_DCDC_Matchingcode_08 "MBMU发送给DCDC的DCDC的匹配码";
CM_ SG_ 2148892488 M2D_IDX_Reserved_08 "预留";
CM_ SG_ 2148892489 M2D_CMD2_CRC_09 "CRC校验";
CM_ SG_ 2148892489 M2D_IDX_CMD_Type_09 "MBMU发送给DCDC的自动编码命令类型";
CM_ SG_ 2148892489 M2D_IDX_DCDC_Index_09 "MBMU发送给DCDC的DCDC的编码地址";
CM_ SG_ 2148892489 M2D_IDX_DCDC_Matchingcode_09 "MBMU发送给DCDC的DCDC的匹配码";
CM_ SG_ 2148892489 M2D_IDX_Reserved_09 "预留";
CM_ SG_ 2148892490 M2D_CMD2_CRC_10 "CRC校验";
CM_ SG_ 2148892490 M2D_IDX_CMD_Type_10 "MBMU发送给DCDC的自动编码命令类型";
CM_ SG_ 2148892490 M2D_IDX_DCDC_Index_10 "MBMU发送给DCDC的DCDC的编码地址";
CM_ SG_ 2148892490 M2D_IDX_DCDC_Matchingcode_10 "MBMU发送给DCDC的DCDC的匹配码";
CM_ SG_ 2148892490 M2D_IDX_Reserved_10 "预留";
CM_ SG_ 2148892491 M2D_CMD2_CRC_11 "CRC校验";
CM_ SG_ 2148892491 M2D_IDX_CMD_Type_11 "MBMU发送给DCDC的自动编码命令类型";
CM_ SG_ 2148892491 M2D_IDX_DCDC_Index_11 "MBMU发送给DCDC的DCDC的编码地址";
CM_ SG_ 2148892491 M2D_IDX_DCDC_Matchingcode_11 "MBMU发送给DCDC的DCDC的匹配码";
CM_ SG_ 2148892491 M2D_IDX_Reserved_11 "预留";
CM_ SG_ 2148892492 M2D_CMD2_CRC_12 "CRC校验";
CM_ SG_ 2148892492 M2D_IDX_CMD_Type_12 "MBMU发送给DCDC的自动编码命令类型";
CM_ SG_ 2148892492 M2D_IDX_DCDC_Index_12 "MBMU发送给DCDC的DCDC的编码地址";
CM_ SG_ 2148892492 M2D_IDX_DCDC_Matchingcode_12 "MBMU发送给DCDC的DCDC的匹配码";
CM_ SG_ 2148892492 M2D_IDX_Reserved_12 "预留";
CM_ SG_ 2148892493 M2D_CMD2_CRC_13 "CRC校验";
CM_ SG_ 2148892493 M2D_IDX_CMD_Type_13 "MBMU发送给DCDC的自动编码命令类型";
CM_ SG_ 2148892493 M2D_IDX_DCDC_Index_13 "MBMU发送给DCDC的DCDC的编码地址";
CM_ SG_ 2148892493 M2D_IDX_DCDC_Matchingcode_13 "MBMU发送给DCDC的DCDC的匹配码";
CM_ SG_ 2148892493 M2D_IDX_Reserved_13 "预留";
CM_ SG_ 2148892494 M2D_CMD2_CRC_14 "CRC校验";
CM_ SG_ 2148892494 M2D_IDX_CMD_Type_14 "MBMU发送给DCDC的自动编码命令类型";
CM_ SG_ 2148892494 M2D_IDX_DCDC_Index_14 "MBMU发送给DCDC的DCDC的编码地址";
CM_ SG_ 2148892494 M2D_IDX_DCDC_Matchingcode_14 "MBMU发送给DCDC的DCDC的匹配码";
CM_ SG_ 2148892494 M2D_IDX_Reserved_14 "预留";
CM_ SG_ 2148892495 M2D_CMD2_CRC_15 "CRC校验";
CM_ SG_ 2148892495 M2D_IDX_CMD_Type_15 "MBMU发送给DCDC的自动编码命令类型";
CM_ SG_ 2148892495 M2D_IDX_DCDC_Index_15 "MBMU发送给DCDC的DCDC的编码地址";
CM_ SG_ 2148892495 M2D_IDX_DCDC_Matchingcode_15 "MBMU发送给DCDC的DCDC的匹配码";
CM_ SG_ 2148892495 M2D_IDX_Reserved_15 "预留";
CM_ SG_ 2148892496 M2D_CMD2_CRC_16 "CRC校验";
CM_ SG_ 2148892496 M2D_IDX_CMD_Type_16 "MBMU发送给DCDC的自动编码命令类型";
CM_ SG_ 2148892496 M2D_IDX_DCDC_Index_16 "MBMU发送给DCDC的DCDC的编码地址";
CM_ SG_ 2148892496 M2D_IDX_DCDC_Matchingcode_16 "MBMU发送给DCDC的DCDC的匹配码";
CM_ SG_ 2148892496 M2D_IDX_Reserved_16 "预留";
CM_ SG_ 2148892497 M2D_CMD2_CRC_17 "CRC校验";
CM_ SG_ 2148892497 M2D_IDX_CMD_Type_17 "MBMU发送给DCDC的自动编码命令类型";
CM_ SG_ 2148892497 M2D_IDX_DCDC_Index_17 "MBMU发送给DCDC的DCDC的编码地址";
CM_ SG_ 2148892497 M2D_IDX_DCDC_Matchingcode_17 "MBMU发送给DCDC的DCDC的匹配码";
CM_ SG_ 2148892497 M2D_IDX_Reserved_17 "预留";
CM_ SG_ 2148892498 M2D_CMD2_CRC_18 "CRC校验";
CM_ SG_ 2148892498 M2D_IDX_CMD_Type_18 "MBMU发送给DCDC的自动编码命令类型";
CM_ SG_ 2148892498 M2D_IDX_DCDC_Index_18 "MBMU发送给DCDC的DCDC的编码地址";
CM_ SG_ 2148892498 M2D_IDX_DCDC_Matchingcode_18 "MBMU发送给DCDC的DCDC的匹配码";
CM_ SG_ 2148892498 M2D_IDX_Reserved_18 "预留";
CM_ SG_ 2148892499 M2D_CMD2_CRC_19 "CRC校验";
CM_ SG_ 2148892499 M2D_IDX_CMD_Type_19 "MBMU发送给DCDC的自动编码命令类型";
CM_ SG_ 2148892499 M2D_IDX_DCDC_Index_19 "MBMU发送给DCDC的DCDC的编码地址";
CM_ SG_ 2148892499 M2D_IDX_DCDC_Matchingcode_19 "MBMU发送给DCDC的DCDC的匹配码";
CM_ SG_ 2148892499 M2D_IDX_Reserved_19 "预留";
CM_ SG_ 2148892500 M2D_CMD2_CRC_20 "CRC校验";
CM_ SG_ 2148892500 M2D_IDX_CMD_Type_20 "MBMU发送给DCDC的自动编码命令类型";
CM_ SG_ 2148892500 M2D_IDX_DCDC_Index_20 "MBMU发送给DCDC的DCDC的编码地址";
CM_ SG_ 2148892500 M2D_IDX_DCDC_Matchingcode_20 "MBMU发送给DCDC的DCDC的匹配码";
CM_ SG_ 2148892500 M2D_IDX_Reserved_20 "预留";
CM_ SG_ 2148892501 M2D_CMD2_CRC_21 "CRC校验";
CM_ SG_ 2148892501 M2D_IDX_CMD_Type_21 "MBMU发送给DCDC的自动编码命令类型";
CM_ SG_ 2148892501 M2D_IDX_DCDC_Index_21 "MBMU发送给DCDC的DCDC的编码地址";
CM_ SG_ 2148892501 M2D_IDX_DCDC_Matchingcode_21 "MBMU发送给DCDC的DCDC的匹配码";
CM_ SG_ 2148892501 M2D_IDX_Reserved_21 "预留";
CM_ SG_ 2148892502 M2D_CMD2_CRC_22 "CRC校验";
CM_ SG_ 2148892502 M2D_IDX_CMD_Type_22 "MBMU发送给DCDC的自动编码命令类型";
CM_ SG_ 2148892502 M2D_IDX_DCDC_Index_22 "MBMU发送给DCDC的DCDC的编码地址";
CM_ SG_ 2148892502 M2D_IDX_DCDC_Matchingcode_22 "MBMU发送给DCDC的DCDC的匹配码";
CM_ SG_ 2148892502 M2D_IDX_Reserved_22 "预留";
CM_ SG_ 2148892503 M2D_CMD2_CRC_23 "CRC校验";
CM_ SG_ 2148892503 M2D_IDX_CMD_Type_23 "MBMU发送给DCDC的自动编码命令类型";
CM_ SG_ 2148892503 M2D_IDX_DCDC_Index_23 "MBMU发送给DCDC的DCDC的编码地址";
CM_ SG_ 2148892503 M2D_IDX_DCDC_Matchingcode_23 "MBMU发送给DCDC的DCDC的匹配码";
CM_ SG_ 2148892503 M2D_IDX_Reserved_23 "预留";
CM_ SG_ 2148892504 M2D_CMD2_CRC_24 "CRC校验";
CM_ SG_ 2148892504 M2D_IDX_CMD_Type_24 "MBMU发送给DCDC的自动编码命令类型";
CM_ SG_ 2148892504 M2D_IDX_DCDC_Index_24 "MBMU发送给DCDC的DCDC的编码地址";
CM_ SG_ 2148892504 M2D_IDX_DCDC_Matchingcode_24 "MBMU发送给DCDC的DCDC的匹配码";
CM_ SG_ 2148892504 M2D_IDX_Reserved_24 "预留";
CM_ SG_ 2148892505 M2D_CMD2_CRC_25 "CRC校验";
CM_ SG_ 2148892505 M2D_IDX_CMD_Type_25 "MBMU发送给DCDC的自动编码命令类型";
CM_ SG_ 2148892505 M2D_IDX_DCDC_Index_25 "MBMU发送给DCDC的DCDC的编码地址";
CM_ SG_ 2148892505 M2D_IDX_DCDC_Matchingcode_25 "MBMU发送给DCDC的DCDC的匹配码";
CM_ SG_ 2148892505 M2D_IDX_Reserved_25 "预留";
CM_ SG_ 2148892506 M2D_CMD2_CRC_26 "CRC校验";
CM_ SG_ 2148892506 M2D_IDX_CMD_Type_26 "MBMU发送给DCDC的自动编码命令类型";
CM_ SG_ 2148892506 M2D_IDX_DCDC_Index_26 "MBMU发送给DCDC的DCDC的编码地址";
CM_ SG_ 2148892506 M2D_IDX_DCDC_Matchingcode_26 "MBMU发送给DCDC的DCDC的匹配码";
CM_ SG_ 2148892506 M2D_IDX_Reserved_26 "预留";
CM_ SG_ 2148892507 M2D_CMD2_CRC_27 "CRC校验";
CM_ SG_ 2148892507 M2D_IDX_CMD_Type_27 "MBMU发送给DCDC的自动编码命令类型";
CM_ SG_ 2148892507 M2D_IDX_DCDC_Index_27 "MBMU发送给DCDC的DCDC的编码地址";
CM_ SG_ 2148892507 M2D_IDX_DCDC_Matchingcode_27 "MBMU发送给DCDC的DCDC的匹配码";
CM_ SG_ 2148892507 M2D_IDX_Reserved_27 "预留";
CM_ SG_ 2148892508 M2D_CMD2_CRC_28 "CRC校验";
CM_ SG_ 2148892508 M2D_IDX_CMD_Type_28 "MBMU发送给DCDC的自动编码命令类型";
CM_ SG_ 2148892508 M2D_IDX_DCDC_Index_28 "MBMU发送给DCDC的DCDC的编码地址";
CM_ SG_ 2148892508 M2D_IDX_DCDC_Matchingcode_28 "MBMU发送给DCDC的DCDC的匹配码";
CM_ SG_ 2148892508 M2D_IDX_Reserved_28 "预留";
CM_ SG_ 2148892509 M2D_CMD2_CRC_29 "CRC校验";
CM_ SG_ 2148892509 M2D_IDX_CMD_Type_29 "MBMU发送给DCDC的自动编码命令类型";
CM_ SG_ 2148892509 M2D_IDX_DCDC_Index_29 "MBMU发送给DCDC的DCDC的编码地址";
CM_ SG_ 2148892509 M2D_IDX_DCDC_Matchingcode_29 "MBMU发送给DCDC的DCDC的匹配码";
CM_ SG_ 2148892509 M2D_IDX_Reserved_29 "预留";
CM_ SG_ 2148892510 M2D_CMD2_CRC_30 "CRC校验";
CM_ SG_ 2148892510 M2D_IDX_CMD_Type_30 "MBMU发送给DCDC的自动编码命令类型";
CM_ SG_ 2148892510 M2D_IDX_DCDC_Index_30 "MBMU发送给DCDC的DCDC的编码地址";
CM_ SG_ 2148892510 M2D_IDX_DCDC_Matchingcode_30 "MBMU发送给DCDC的DCDC的匹配码";
CM_ SG_ 2148892510 M2D_IDX_Reserved_30 "预留";
CM_ SG_ 2148892511 M2D_CMD2_CRC_31 "CRC校验";
CM_ SG_ 2148892511 M2D_IDX_CMD_Type_31 "MBMU发送给DCDC的自动编码命令类型";
CM_ SG_ 2148892511 M2D_IDX_DCDC_Index_31 "MBMU发送给DCDC的DCDC的编码地址";
CM_ SG_ 2148892511 M2D_IDX_DCDC_Matchingcode_31 "MBMU发送给DCDC的DCDC的匹配码";
CM_ SG_ 2148892511 M2D_IDX_Reserved_31 "预留";
CM_ SG_ 2148892512 M2D_CMD2_CRC_32 "CRC校验";
CM_ SG_ 2148892512 M2D_IDX_CMD_Type_32 "MBMU发送给DCDC的自动编码命令类型";
CM_ SG_ 2148892512 M2D_IDX_DCDC_Index_32 "MBMU发送给DCDC的DCDC的编码地址";
CM_ SG_ 2148892512 M2D_IDX_DCDC_Matchingcode_32 "MBMU发送给DCDC的DCDC的匹配码";
CM_ SG_ 2148892512 M2D_IDX_Reserved_32 "预留";
CM_ SG_ 2148892513 M2D_CMD2_CRC_33 "CRC校验";
CM_ SG_ 2148892513 M2D_IDX_CMD_Type_33 "MBMU发送给DCDC的自动编码命令类型";
CM_ SG_ 2148892513 M2D_IDX_DCDC_Index_33 "MBMU发送给DCDC的DCDC的编码地址";
CM_ SG_ 2148892513 M2D_IDX_DCDC_Matchingcode_33 "MBMU发送给DCDC的DCDC的匹配码";
CM_ SG_ 2148892513 M2D_IDX_Reserved_33 "预留";
CM_ SG_ 2148892514 M2D_CMD2_CRC_34 "CRC校验";
CM_ SG_ 2148892514 M2D_IDX_CMD_Type_34 "MBMU发送给DCDC的自动编码命令类型";
CM_ SG_ 2148892514 M2D_IDX_DCDC_Index_34 "MBMU发送给DCDC的DCDC的编码地址";
CM_ SG_ 2148892514 M2D_IDX_DCDC_Matchingcode_34 "MBMU发送给DCDC的DCDC的匹配码";
CM_ SG_ 2148892514 M2D_IDX_Reserved_34 "预留";
CM_ SG_ 2148892515 M2D_CMD2_CRC_35 "CRC校验";
CM_ SG_ 2148892515 M2D_IDX_CMD_Type_35 "MBMU发送给DCDC的自动编码命令类型";
CM_ SG_ 2148892515 M2D_IDX_DCDC_Index_35 "MBMU发送给DCDC的DCDC的编码地址";
CM_ SG_ 2148892515 M2D_IDX_DCDC_Matchingcode_35 "MBMU发送给DCDC的DCDC的匹配码";
CM_ SG_ 2148892515 M2D_IDX_Reserved_35 "预留";
CM_ SG_ 2148892516 M2D_CMD2_CRC_36 "CRC校验";
CM_ SG_ 2148892516 M2D_IDX_CMD_Type_36 "MBMU发送给DCDC的自动编码命令类型";
CM_ SG_ 2148892516 M2D_IDX_DCDC_Index_36 "MBMU发送给DCDC的DCDC的编码地址";
CM_ SG_ 2148892516 M2D_IDX_DCDC_Matchingcode_36 "MBMU发送给DCDC的DCDC的匹配码";
CM_ SG_ 2148892516 M2D_IDX_Reserved_36 "预留";
CM_ SG_ 2148892517 M2D_CMD2_CRC_37 "CRC校验";
CM_ SG_ 2148892517 M2D_IDX_CMD_Type_37 "MBMU发送给DCDC的自动编码命令类型";
CM_ SG_ 2148892517 M2D_IDX_DCDC_Index_37 "MBMU发送给DCDC的DCDC的编码地址";
CM_ SG_ 2148892517 M2D_IDX_DCDC_Matchingcode_37 "MBMU发送给DCDC的DCDC的匹配码";
CM_ SG_ 2148892517 M2D_IDX_Reserved_37 "预留";
CM_ SG_ 2148892518 M2D_CMD2_CRC_38 "CRC校验";
CM_ SG_ 2148892518 M2D_IDX_CMD_Type_38 "MBMU发送给DCDC的自动编码命令类型";
CM_ SG_ 2148892518 M2D_IDX_DCDC_Index_38 "MBMU发送给DCDC的DCDC的编码地址";
CM_ SG_ 2148892518 M2D_IDX_DCDC_Matchingcode_38 "MBMU发送给DCDC的DCDC的匹配码";
CM_ SG_ 2148892518 M2D_IDX_Reserved_38 "预留";
CM_ SG_ 2148892519 M2D_CMD2_CRC_39 "CRC校验";
CM_ SG_ 2148892519 M2D_IDX_CMD_Type_39 "MBMU发送给DCDC的自动编码命令类型";
CM_ SG_ 2148892519 M2D_IDX_DCDC_Index_39 "MBMU发送给DCDC的DCDC的编码地址";
CM_ SG_ 2148892519 M2D_IDX_DCDC_Matchingcode_39 "MBMU发送给DCDC的DCDC的匹配码";
CM_ SG_ 2148892519 M2D_IDX_Reserved_39 "预留";
CM_ SG_ 2148892520 M2D_CMD2_CRC_40 "CRC校验";
CM_ SG_ 2148892520 M2D_IDX_CMD_Type_40 "MBMU发送给DCDC的自动编码命令类型";
CM_ SG_ 2148892520 M2D_IDX_DCDC_Index_40 "MBMU发送给DCDC的DCDC的编码地址";
CM_ SG_ 2148892520 M2D_IDX_DCDC_Matchingcode_40 "MBMU发送给DCDC的DCDC的匹配码";
CM_ SG_ 2148892520 M2D_IDX_Reserved_40 "预留";
VAL_ 2148826952 M2D_CMD1_DCDCEnable_08 0 "Disable" 1 "Enable" ;
VAL_ 2148826952 M2D_CMD1_DCDCWrkMdSwtch_08 0 "Standby" 1 "Normal Run" 2 "Bypass" 3 "Reserved" ;
VAL_ 2148826952 M2D_CMD1_DCDCWrkMdSet_08 0 "Constant Vlotage" 1 "Constant Current" 2 "Steady Current(not greater than)" 3 "Steady Current(not less than)" ;
VAL_ 2148826952 M2D_CMD1_DCDCOutputCrrntSet_08 1276 "Null" ;
VAL_ 2148826952 M2D_CMD1_DCDCOutputVltge_Set_08 209 "Null" ;
VAL_ 2148826952 M2D_CMD1_CommunicationState_08 0 "Normal" 1 "CAN lost" ;
VAL_ 2148826952 M2D_CMD1_DCDCFaultClear_08 0 "Not Clear" 1 "Clear" ;
VAL_ 2148826952 M2D_CMD1_PCSOperationState_08 0 "Standby" 1 "Discharge" 2 "Charge" 3 "Fault" ;
VAL_ 2148826952 M2D_CMD1_DCDCLVoffControl_08 0 "不允许低压下电" 1 "允许低压下电" ;
VAL_ 2148826953 M2D_CMD1_DCDCEnable_09 0 "Disable" 1 "Enable" ;
VAL_ 2148826953 M2D_CMD1_DCDCWrkMdSwtch_09 0 "Standby" 1 "Normal Run" 2 "Bypass" 3 "Reserved" ;
VAL_ 2148826953 M2D_CMD1_DCDCWrkMdSet_09 0 "Constant Vlotage" 1 "Constant Current" 2 "Steady Current(not greater than)" 3 "Steady Current(not less than)" ;
VAL_ 2148826953 M2D_CMD1_DCDCOutputCrrntSet_09 1276 "Null" ;
VAL_ 2148826953 M2D_CMD1_DCDCOutputVltge_Set_09 209 "Null" ;
VAL_ 2148826953 M2D_CMD1_CommunicationState_09 0 "Normal" 1 "CAN lost" ;
VAL_ 2148826953 M2D_CMD1_DCDCFaultClear_09 0 "Not Clear" 1 "Clear" ;
VAL_ 2148826953 M2D_CMD1_PCSOperationState_09 0 "Standby" 1 "Discharge" 2 "Charge" 3 "Fault" ;
VAL_ 2148826953 M2D_CMD1_DCDCLVoffControl_09 0 "不允许低压下电" 1 "允许低压下电" ;
VAL_ 2148826954 M2D_CMD1_DCDCEnable_10 0 "Disable" 1 "Enable" ;
VAL_ 2148826954 M2D_CMD1_DCDCWrkMdSwtch_10 0 "Standby" 1 "Normal Run" 2 "Bypass" 3 "Reserved" ;
VAL_ 2148826954 M2D_CMD1_DCDCWrkMdSet_10 0 "Constant Vlotage" 1 "Constant Current" 2 "Steady Current(not greater than)" 3 "Steady Current(not less than)" ;
VAL_ 2148826954 M2D_CMD1_DCDCOutputCrrntSet_10 1276 "Null" ;
VAL_ 2148826954 M2D_CMD1_DCDCOutputVltge_Set_10 209 "Null" ;
VAL_ 2148826954 M2D_CMD1_CommunicationState_10 0 "Normal" 1 "CAN lost" ;
VAL_ 2148826954 M2D_CMD1_DCDCFaultClear_10 0 "Not Clear" 1 "Clear" ;
VAL_ 2148826954 M2D_CMD1_PCSOperationState_10 0 "Standby" 1 "Discharge" 2 "Charge" 3 "Fault" ;
VAL_ 2148826954 M2D_CMD1_DCDCLVoffControl_10 0 "不允许低压下电" 1 "允许低压下电" ;
VAL_ 2148826955 M2D_CMD1_DCDCEnable_11 0 "Disable" 1 "Enable" ;
VAL_ 2148826955 M2D_CMD1_DCDCWrkMdSwtch_11 0 "Standby" 1 "Normal Run" 2 "Bypass" 3 "Reserved" ;
VAL_ 2148826955 M2D_CMD1_DCDCWrkMdSet_11 0 "Constant Vlotage" 1 "Constant Current" 2 "Steady Current(not greater than)" 3 "Steady Current(not less than)" ;
VAL_ 2148826955 M2D_CMD1_DCDCOutputCrrntSet_11 1276 "Null" ;
VAL_ 2148826955 M2D_CMD1_DCDCOutputVltge_Set_11 209 "Null" ;
VAL_ 2148826955 M2D_CMD1_CommunicationState_11 0 "Normal" 1 "CAN lost" ;
VAL_ 2148826955 M2D_CMD1_DCDCFaultClear_11 0 "Not Clear" 1 "Clear" ;
VAL_ 2148826955 M2D_CMD1_PCSOperationState_11 0 "Standby" 1 "Discharge" 2 "Charge" 3 "Fault" ;
VAL_ 2148826955 M2D_CMD1_DCDCLVoffControl_11 0 "不允许低压下电" 1 "允许低压下电" ;
VAL_ 2148826956 M2D_CMD1_DCDCEnable_12 0 "Disable" 1 "Enable" ;
VAL_ 2148826956 M2D_CMD1_DCDCWrkMdSwtch_12 0 "Standby" 1 "Normal Run" 2 "Bypass" 3 "Reserved" ;
VAL_ 2148826956 M2D_CMD1_DCDCWrkMdSet_12 0 "Constant Vlotage" 1 "Constant Current" 2 "Steady Current(not greater than)" 3 "Steady Current(not less than)" ;
VAL_ 2148826956 M2D_CMD1_DCDCOutputCrrntSet_12 1276 "Null" ;
VAL_ 2148826956 M2D_CMD1_DCDCOutputVltge_Set_12 209 "Null" ;
VAL_ 2148826956 M2D_CMD1_CommunicationState_12 0 "Normal" 1 "CAN lost" ;
VAL_ 2148826956 M2D_CMD1_DCDCFaultClear_12 0 "Not Clear" 1 "Clear" ;
VAL_ 2148826956 M2D_CMD1_PCSOperationState_12 0 "Standby" 1 "Discharge" 2 "Charge" 3 "Fault" ;
VAL_ 2148826956 M2D_CMD1_DCDCLVoffControl_12 0 "不允许低压下电" 1 "允许低压下电" ;
VAL_ 2148826957 M2D_CMD1_DCDCEnable_13 0 "Disable" 1 "Enable" ;
VAL_ 2148826957 M2D_CMD1_DCDCWrkMdSwtch_13 0 "Standby" 1 "Normal Run" 2 "Bypass" 3 "Reserved" ;
VAL_ 2148826957 M2D_CMD1_DCDCWrkMdSet_13 0 "Constant Vlotage" 1 "Constant Current" 2 "Steady Current(not greater than)" 3 "Steady Current(not less than)" ;
VAL_ 2148826957 M2D_CMD1_DCDCOutputCrrntSet_13 1276 "Null" ;
VAL_ 2148826957 M2D_CMD1_DCDCOutputVltge_Set_13 209 "Null" ;
VAL_ 2148826957 M2D_CMD1_CommunicationState_13 0 "Normal" 1 "CAN lost" ;
VAL_ 2148826957 M2D_CMD1_DCDCFaultClear_13 0 "Not Clear" 1 "Clear" ;
VAL_ 2148826957 M2D_CMD1_PCSOperationState_13 0 "Standby" 1 "Discharge" 2 "Charge" 3 "Fault" ;
VAL_ 2148826957 M2D_CMD1_DCDCLVoffControl_13 0 "不允许低压下电" 1 "允许低压下电" ;
VAL_ 2148826958 M2D_CMD1_DCDCEnable_14 0 "Disable" 1 "Enable" ;
VAL_ 2148826958 M2D_CMD1_DCDCWrkMdSwtch_14 0 "Standby" 1 "Normal Run" 2 "Bypass" 3 "Reserved" ;
VAL_ 2148826958 M2D_CMD1_DCDCWrkMdSet_14 0 "Constant Vlotage" 1 "Constant Current" 2 "Steady Current(not greater than)" 3 "Steady Current(not less than)" ;
VAL_ 2148826958 M2D_CMD1_DCDCOutputCrrntSet_14 1276 "Null" ;
VAL_ 2148826958 M2D_CMD1_DCDCOutputVltge_Set_14 209 "Null" ;
VAL_ 2148826958 M2D_CMD1_CommunicationState_14 0 "Normal" 1 "CAN lost" ;
VAL_ 2148826958 M2D_CMD1_DCDCFaultClear_14 0 "Not Clear" 1 "Clear" ;
VAL_ 2148826958 M2D_CMD1_PCSOperationState_14 0 "Standby" 1 "Discharge" 2 "Charge" 3 "Fault" ;
VAL_ 2148826958 M2D_CMD1_DCDCLVoffControl_14 0 "不允许低压下电" 1 "允许低压下电" ;
VAL_ 2148826959 M2D_CMD1_DCDCEnable_15 0 "Disable" 1 "Enable" ;
VAL_ 2148826959 M2D_CMD1_DCDCWrkMdSwtch_15 0 "Standby" 1 "Normal Run" 2 "Bypass" 3 "Reserved" ;
VAL_ 2148826959 M2D_CMD1_DCDCWrkMdSet_15 0 "Constant Vlotage" 1 "Constant Current" 2 "Steady Current(not greater than)" 3 "Steady Current(not less than)" ;
VAL_ 2148826959 M2D_CMD1_DCDCOutputCrrntSet_15 1276 "Null" ;
VAL_ 2148826959 M2D_CMD1_DCDCOutputVltge_Set_15 209 "Null" ;
VAL_ 2148826959 M2D_CMD1_CommunicationState_15 0 "Normal" 1 "CAN lost" ;
VAL_ 2148826959 M2D_CMD1_DCDCFaultClear_15 0 "Not Clear" 1 "Clear" ;
VAL_ 2148826959 M2D_CMD1_PCSOperationState_15 0 "Standby" 1 "Discharge" 2 "Charge" 3 "Fault" ;
VAL_ 2148826959 M2D_CMD1_DCDCLVoffControl_15 0 "不允许低压下电" 1 "允许低压下电" ;
VAL_ 2148826960 M2D_CMD1_DCDCEnable_16 0 "Disable" 1 "Enable" ;
VAL_ 2148826960 M2D_CMD1_DCDCWrkMdSwtch_16 0 "Standby" 1 "Normal Run" 2 "Bypass" 3 "Reserved" ;
VAL_ 2148826960 M2D_CMD1_DCDCWrkMdSet_16 0 "Constant Vlotage" 1 "Constant Current" 2 "Steady Current(not greater than)" 3 "Steady Current(not less than)" ;
VAL_ 2148826960 M2D_CMD1_DCDCOutputCrrntSet_16 1276 "Null" ;
VAL_ 2148826960 M2D_CMD1_DCDCOutputVltge_Set_16 209 "Null" ;
VAL_ 2148826960 M2D_CMD1_CommunicationState_16 0 "Normal" 1 "CAN lost" ;
VAL_ 2148826960 M2D_CMD1_DCDCFaultClear_16 0 "Not Clear" 1 "Clear" ;
VAL_ 2148826960 M2D_CMD1_PCSOperationState_16 0 "Standby" 1 "Discharge" 2 "Charge" 3 "Fault" ;
VAL_ 2148826960 M2D_CMD1_DCDCLVoffControl_16 0 "不允许低压下电" 1 "允许低压下电" ;
VAL_ 2148826961 M2D_CMD1_DCDCEnable_17 0 "Disable" 1 "Enable" ;
VAL_ 2148826961 M2D_CMD1_DCDCWrkMdSwtch_17 0 "Standby" 1 "Normal Run" 2 "Bypass" 3 "Reserved" ;
VAL_ 2148826961 M2D_CMD1_DCDCWrkMdSet_17 0 "Constant Vlotage" 1 "Constant Current" 2 "Steady Current(not greater than)" 3 "Steady Current(not less than)" ;
VAL_ 2148826961 M2D_CMD1_DCDCOutputCrrntSet_17 1276 "Null" ;
VAL_ 2148826961 M2D_CMD1_DCDCOutputVltge_Set_17 209 "Null" ;
VAL_ 2148826961 M2D_CMD1_CommunicationState_17 0 "Normal" 1 "CAN lost" ;
VAL_ 2148826961 M2D_CMD1_DCDCFaultClear_17 0 "Not Clear" 1 "Clear" ;
VAL_ 2148826961 M2D_CMD1_PCSOperationState_17 0 "Standby" 1 "Discharge" 2 "Charge" 3 "Fault" ;
VAL_ 2148826961 M2D_CMD1_DCDCLVoffControl_17 0 "不允许低压下电" 1 "允许低压下电" ;
VAL_ 2148826962 M2D_CMD1_DCDCEnable_18 0 "Disable" 1 "Enable" ;
VAL_ 2148826962 M2D_CMD1_DCDCWrkMdSwtch_18 0 "Standby" 1 "Normal Run" 2 "Bypass" 3 "Reserved" ;
VAL_ 2148826962 M2D_CMD1_DCDCWrkMdSet_18 0 "Constant Vlotage" 1 "Constant Current" 2 "Steady Current(not greater than)" 3 "Steady Current(not less than)" ;
VAL_ 2148826962 M2D_CMD1_DCDCOutputCrrntSet_18 1276 "Null" ;
VAL_ 2148826962 M2D_CMD1_DCDCOutputVltge_Set_18 209 "Null" ;
VAL_ 2148826962 M2D_CMD1_CommunicationState_18 0 "Normal" 1 "CAN lost" ;
VAL_ 2148826962 M2D_CMD1_DCDCFaultClear_18 0 "Not Clear" 1 "Clear" ;
VAL_ 2148826962 M2D_CMD1_PCSOperationState_18 0 "Standby" 1 "Discharge" 2 "Charge" 3 "Fault" ;
VAL_ 2148826962 M2D_CMD1_DCDCLVoffControl_18 0 "不允许低压下电" 1 "允许低压下电" ;
VAL_ 2148826963 M2D_CMD1_DCDCEnable_19 0 "Disable" 1 "Enable" ;
VAL_ 2148826963 M2D_CMD1_DCDCWrkMdSwtch_19 0 "Standby" 1 "Normal Run" 2 "Bypass" 3 "Reserved" ;
VAL_ 2148826963 M2D_CMD1_DCDCWrkMdSet_19 0 "Constant Vlotage" 1 "Constant Current" 2 "Steady Current(not greater than)" 3 "Steady Current(not less than)" ;
VAL_ 2148826963 M2D_CMD1_DCDCOutputCrrntSet_19 1276 "Null" ;
VAL_ 2148826963 M2D_CMD1_DCDCOutputVltge_Set_19 209 "Null" ;
VAL_ 2148826963 M2D_CMD1_CommunicationState_19 0 "Normal" 1 "CAN lost" ;
VAL_ 2148826963 M2D_CMD1_DCDCFaultClear_19 0 "Not Clear" 1 "Clear" ;
VAL_ 2148826963 M2D_CMD1_PCSOperationState_19 0 "Standby" 1 "Discharge" 2 "Charge" 3 "Fault" ;
VAL_ 2148826963 M2D_CMD1_DCDCLVoffControl_19 0 "不允许低压下电" 1 "允许低压下电" ;
VAL_ 2148826964 M2D_CMD1_DCDCEnable_20 0 "Disable" 1 "Enable" ;
VAL_ 2148826964 M2D_CMD1_DCDCWrkMdSwtch_20 0 "Standby" 1 "Normal Run" 2 "Bypass" 3 "Reserved" ;
VAL_ 2148826964 M2D_CMD1_DCDCWrkMdSet_20 0 "Constant Vlotage" 1 "Constant Current" 2 "Steady Current(not greater than)" 3 "Steady Current(not less than)" ;
VAL_ 2148826964 M2D_CMD1_DCDCOutputCrrntSet_20 1276 "Null" ;
VAL_ 2148826964 M2D_CMD1_DCDCOutputVltge_Set_20 209 "Null" ;
VAL_ 2148826964 M2D_CMD1_CommunicationState_20 0 "Normal" 1 "CAN lost" ;
VAL_ 2148826964 M2D_CMD1_DCDCFaultClear_20 0 "Not Clear" 1 "Clear" ;
VAL_ 2148826964 M2D_CMD1_PCSOperationState_20 0 "Standby" 1 "Discharge" 2 "Charge" 3 "Fault" ;
VAL_ 2148826964 M2D_CMD1_DCDCLVoffControl_20 0 "不允许低压下电" 1 "允许低压下电" ;
VAL_ 2148826965 M2D_CMD1_DCDCEnable_21 0 "Disable" 1 "Enable" ;
VAL_ 2148826965 M2D_CMD1_DCDCWrkMdSwtch_21 0 "Standby" 1 "Normal Run" 2 "Bypass" 3 "Reserved" ;
VAL_ 2148826965 M2D_CMD1_DCDCWrkMdSet_21 0 "Constant Vlotage" 1 "Constant Current" 2 "Steady Current(not greater than)" 3 "Steady Current(not less than)" ;
VAL_ 2148826965 M2D_CMD1_DCDCOutputCrrntSet_21 1276 "Null" ;
VAL_ 2148826965 M2D_CMD1_DCDCOutputVltge_Set_21 209 "Null" ;
VAL_ 2148826965 M2D_CMD1_CommunicationState_21 0 "Normal" 1 "CAN lost" ;
VAL_ 2148826965 M2D_CMD1_DCDCFaultClear_21 0 "Not Clear" 1 "Clear" ;
VAL_ 2148826965 M2D_CMD1_PCSOperationState_21 0 "Standby" 1 "Discharge" 2 "Charge" 3 "Fault" ;
VAL_ 2148826965 M2D_CMD1_DCDCLVoffControl_21 0 "不允许低压下电" 1 "允许低压下电" ;
VAL_ 2148826966 M2D_CMD1_DCDCEnable_22 0 "Disable" 1 "Enable" ;
VAL_ 2148826966 M2D_CMD1_DCDCWrkMdSwtch_22 0 "Standby" 1 "Normal Run" 2 "Bypass" 3 "Reserved" ;
VAL_ 2148826966 M2D_CMD1_DCDCWrkMdSet_22 0 "Constant Vlotage" 1 "Constant Current" 2 "Steady Current(not greater than)" 3 "Steady Current(not less than)" ;
VAL_ 2148826966 M2D_CMD1_DCDCOutputCrrntSet_22 1276 "Null" ;
VAL_ 2148826966 M2D_CMD1_DCDCOutputVltge_Set_22 209 "Null" ;
VAL_ 2148826966 M2D_CMD1_CommunicationState_22 0 "Normal" 1 "CAN lost" ;
VAL_ 2148826966 M2D_CMD1_DCDCFaultClear_22 0 "Not Clear" 1 "Clear" ;
VAL_ 2148826966 M2D_CMD1_PCSOperationState_22 0 "Standby" 1 "Discharge" 2 "Charge" 3 "Fault" ;
VAL_ 2148826966 M2D_CMD1_DCDCLVoffControl_22 0 "不允许低压下电" 1 "允许低压下电" ;
VAL_ 2148826967 M2D_CMD1_DCDCEnable_23 0 "Disable" 1 "Enable" ;
VAL_ 2148826967 M2D_CMD1_DCDCWrkMdSwtch_23 0 "Standby" 1 "Normal Run" 2 "Bypass" 3 "Reserved" ;
VAL_ 2148826967 M2D_CMD1_DCDCWrkMdSet_23 0 "Constant Vlotage" 1 "Constant Current" 2 "Steady Current(not greater than)" 3 "Steady Current(not less than)" ;
VAL_ 2148826967 M2D_CMD1_DCDCOutputCrrntSet_23 1276 "Null" ;
VAL_ 2148826967 M2D_CMD1_DCDCOutputVltge_Set_23 209 "Null" ;
VAL_ 2148826967 M2D_CMD1_CommunicationState_23 0 "Normal" 1 "CAN lost" ;
VAL_ 2148826967 M2D_CMD1_DCDCFaultClear_23 0 "Not Clear" 1 "Clear" ;
VAL_ 2148826967 M2D_CMD1_PCSOperationState_23 0 "Standby" 1 "Discharge" 2 "Charge" 3 "Fault" ;
VAL_ 2148826967 M2D_CMD1_DCDCLVoffControl_23 0 "不允许低压下电" 1 "允许低压下电" ;
VAL_ 2148826968 M2D_CMD1_DCDCEnable_24 0 "Disable" 1 "Enable" ;
VAL_ 2148826968 M2D_CMD1_DCDCWrkMdSwtch_24 0 "Standby" 1 "Normal Run" 2 "Bypass" 3 "Reserved" ;
VAL_ 2148826968 M2D_CMD1_DCDCWrkMdSet_24 0 "Constant Vlotage" 1 "Constant Current" 2 "Steady Current(not greater than)" 3 "Steady Current(not less than)" ;
VAL_ 2148826968 M2D_CMD1_DCDCOutputCrrntSet_24 1276 "Null" ;
VAL_ 2148826968 M2D_CMD1_DCDCOutputVltge_Set_24 209 "Null" ;
VAL_ 2148826968 M2D_CMD1_CommunicationState_24 0 "Normal" 1 "CAN lost" ;
VAL_ 2148826968 M2D_CMD1_DCDCFaultClear_24 0 "Not Clear" 1 "Clear" ;
VAL_ 2148826968 M2D_CMD1_PCSOperationState_24 0 "Standby" 1 "Discharge" 2 "Charge" 3 "Fault" ;
VAL_ 2148826968 M2D_CMD1_DCDCLVoffControl_24 0 "不允许低压下电" 1 "允许低压下电" ;
VAL_ 2148826969 M2D_CMD1_DCDCEnable_25 0 "Disable" 1 "Enable" ;
VAL_ 2148826969 M2D_CMD1_DCDCWrkMdSwtch_25 0 "Standby" 1 "Normal Run" 2 "Bypass" 3 "Reserved" ;
VAL_ 2148826969 M2D_CMD1_DCDCWrkMdSet_25 0 "Constant Vlotage" 1 "Constant Current" 2 "Steady Current(not greater than)" 3 "Steady Current(not less than)" ;
VAL_ 2148826969 M2D_CMD1_DCDCOutputCrrntSet_25 1276 "Null" ;
VAL_ 2148826969 M2D_CMD1_DCDCOutputVltge_Set_25 209 "Null" ;
VAL_ 2148826969 M2D_CMD1_CommunicationState_25 0 "Normal" 1 "CAN lost" ;
VAL_ 2148826969 M2D_CMD1_DCDCFaultClear_25 0 "Not Clear" 1 "Clear" ;
VAL_ 2148826969 M2D_CMD1_PCSOperationState_25 0 "Standby" 1 "Discharge" 2 "Charge" 3 "Fault" ;
VAL_ 2148826969 M2D_CMD1_DCDCLVoffControl_25 0 "不允许低压下电" 1 "允许低压下电" ;
VAL_ 2148826970 M2D_CMD1_DCDCEnable_26 0 "Disable" 1 "Enable" ;
VAL_ 2148826970 M2D_CMD1_DCDCWrkMdSwtch_26 0 "Standby" 1 "Normal Run" 2 "Bypass" 3 "Reserved" ;
VAL_ 2148826970 M2D_CMD1_DCDCWrkMdSet_26 0 "Constant Vlotage" 1 "Constant Current" 2 "Steady Current(not greater than)" 3 "Steady Current(not less than)" ;
VAL_ 2148826970 M2D_CMD1_DCDCOutputCrrntSet_26 1276 "Null" ;
VAL_ 2148826970 M2D_CMD1_DCDCOutputVltge_Set_26 209 "Null" ;
VAL_ 2148826970 M2D_CMD1_CommunicationState_26 0 "Normal" 1 "CAN lost" ;
VAL_ 2148826970 M2D_CMD1_DCDCFaultClear_26 0 "Not Clear" 1 "Clear" ;
VAL_ 2148826970 M2D_CMD1_PCSOperationState_26 0 "Standby" 1 "Discharge" 2 "Charge" 3 "Fault" ;
VAL_ 2148826970 M2D_CMD1_DCDCLVoffControl_26 0 "不允许低压下电" 1 "允许低压下电" ;
VAL_ 2148826971 M2D_CMD1_DCDCEnable_27 0 "Disable" 1 "Enable" ;
VAL_ 2148826971 M2D_CMD1_DCDCWrkMdSwtch_27 0 "Standby" 1 "Normal Run" 2 "Bypass" 3 "Reserved" ;
VAL_ 2148826971 M2D_CMD1_DCDCWrkMdSet_27 0 "Constant Vlotage" 1 "Constant Current" 2 "Steady Current(not greater than)" 3 "Steady Current(not less than)" ;
VAL_ 2148826971 M2D_CMD1_DCDCOutputCrrntSet_27 1276 "Null" ;
VAL_ 2148826971 M2D_CMD1_DCDCOutputVltge_Set_27 209 "Null" ;
VAL_ 2148826971 M2D_CMD1_CommunicationState_27 0 "Normal" 1 "CAN lost" ;
VAL_ 2148826971 M2D_CMD1_DCDCFaultClear_27 0 "Not Clear" 1 "Clear" ;
VAL_ 2148826971 M2D_CMD1_PCSOperationState_27 0 "Standby" 1 "Discharge" 2 "Charge" 3 "Fault" ;
VAL_ 2148826971 M2D_CMD1_DCDCLVoffControl_27 0 "不允许低压下电" 1 "允许低压下电" ;
VAL_ 2148826972 M2D_CMD1_DCDCEnable_28 0 "Disable" 1 "Enable" ;
VAL_ 2148826972 M2D_CMD1_DCDCWrkMdSwtch_28 0 "Standby" 1 "Normal Run" 2 "Bypass" 3 "Reserved" ;
VAL_ 2148826972 M2D_CMD1_DCDCWrkMdSet_28 0 "Constant Vlotage" 1 "Constant Current" 2 "Steady Current(not greater than)" 3 "Steady Current(not less than)" ;
VAL_ 2148826972 M2D_CMD1_DCDCOutputCrrntSet_28 1276 "Null" ;
VAL_ 2148826972 M2D_CMD1_DCDCOutputVltge_Set_28 209 "Null" ;
VAL_ 2148826972 M2D_CMD1_CommunicationState_28 0 "Normal" 1 "CAN lost" ;
VAL_ 2148826972 M2D_CMD1_DCDCFaultClear_28 0 "Not Clear" 1 "Clear" ;
VAL_ 2148826972 M2D_CMD1_PCSOperationState_28 0 "Standby" 1 "Discharge" 2 "Charge" 3 "Fault" ;
VAL_ 2148826972 M2D_CMD1_DCDCLVoffControl_28 0 "不允许低压下电" 1 "允许低压下电" ;
VAL_ 2148826973 M2D_CMD1_DCDCEnable_29 0 "Disable" 1 "Enable" ;
VAL_ 2148826973 M2D_CMD1_DCDCWrkMdSwtch_29 0 "Standby" 1 "Normal Run" 2 "Bypass" 3 "Reserved" ;
VAL_ 2148826973 M2D_CMD1_DCDCWrkMdSet_29 0 "Constant Vlotage" 1 "Constant Current" 2 "Steady Current(not greater than)" 3 "Steady Current(not less than)" ;
VAL_ 2148826973 M2D_CMD1_DCDCOutputCrrntSet_29 1276 "Null" ;
VAL_ 2148826973 M2D_CMD1_DCDCOutputVltge_Set_29 209 "Null" ;
VAL_ 2148826973 M2D_CMD1_CommunicationState_29 0 "Normal" 1 "CAN lost" ;
VAL_ 2148826973 M2D_CMD1_DCDCFaultClear_29 0 "Not Clear" 1 "Clear" ;
VAL_ 2148826973 M2D_CMD1_PCSOperationState_29 0 "Standby" 1 "Discharge" 2 "Charge" 3 "Fault" ;
VAL_ 2148826973 M2D_CMD1_DCDCLVoffControl_29 0 "不允许低压下电" 1 "允许低压下电" ;
VAL_ 2148826974 M2D_CMD1_DCDCEnable_30 0 "Disable" 1 "Enable" ;
VAL_ 2148826974 M2D_CMD1_DCDCWrkMdSwtch_30 0 "Standby" 1 "Normal Run" 2 "Bypass" 3 "Reserved" ;
VAL_ 2148826974 M2D_CMD1_DCDCWrkMdSet_30 0 "Constant Vlotage" 1 "Constant Current" 2 "Steady Current(not greater than)" 3 "Steady Current(not less than)" ;
VAL_ 2148826974 M2D_CMD1_DCDCOutputCrrntSet_30 1276 "Null" ;
VAL_ 2148826974 M2D_CMD1_DCDCOutputVltge_Set_30 209 "Null" ;
VAL_ 2148826974 M2D_CMD1_CommunicationState_30 0 "Normal" 1 "CAN lost" ;
VAL_ 2148826974 M2D_CMD1_DCDCFaultClear_30 0 "Not Clear" 1 "Clear" ;
VAL_ 2148826974 M2D_CMD1_PCSOperationState_30 0 "Standby" 1 "Discharge" 2 "Charge" 3 "Fault" ;
VAL_ 2148826974 M2D_CMD1_DCDCLVoffControl_30 0 "不允许低压下电" 1 "允许低压下电" ;
VAL_ 2148826975 M2D_CMD1_DCDCEnable_31 0 "Disable" 1 "Enable" ;
VAL_ 2148826975 M2D_CMD1_DCDCWrkMdSwtch_31 0 "Standby" 1 "Normal Run" 2 "Bypass" 3 "Reserved" ;
VAL_ 2148826975 M2D_CMD1_DCDCWrkMdSet_31 0 "Constant Vlotage" 1 "Constant Current" 2 "Steady Current(not greater than)" 3 "Steady Current(not less than)" ;
VAL_ 2148826975 M2D_CMD1_DCDCOutputCrrntSet_31 1276 "Null" ;
VAL_ 2148826975 M2D_CMD1_DCDCOutputVltge_Set_31 209 "Null" ;
VAL_ 2148826975 M2D_CMD1_CommunicationState_31 0 "Normal" 1 "CAN lost" ;
VAL_ 2148826975 M2D_CMD1_DCDCFaultClear_31 0 "Not Clear" 1 "Clear" ;
VAL_ 2148826975 M2D_CMD1_PCSOperationState_31 0 "Standby" 1 "Discharge" 2 "Charge" 3 "Fault" ;
VAL_ 2148826975 M2D_CMD1_DCDCLVoffControl_31 0 "不允许低压下电" 1 "允许低压下电" ;
VAL_ 2148826976 M2D_CMD1_DCDCEnable_32 0 "Disable" 1 "Enable" ;
VAL_ 2148826976 M2D_CMD1_DCDCWrkMdSwtch_32 0 "Standby" 1 "Normal Run" 2 "Bypass" 3 "Reserved" ;
VAL_ 2148826976 M2D_CMD1_DCDCWrkMdSet_32 0 "Constant Vlotage" 1 "Constant Current" 2 "Steady Current(not greater than)" 3 "Steady Current(not less than)" ;
VAL_ 2148826976 M2D_CMD1_DCDCOutputCrrntSet_32 1276 "Null" ;
VAL_ 2148826976 M2D_CMD1_DCDCOutputVltge_Set_32 209 "Null" ;
VAL_ 2148826976 M2D_CMD1_CommunicationState_32 0 "Normal" 1 "CAN lost" ;
VAL_ 2148826976 M2D_CMD1_DCDCFaultClear_32 0 "Not Clear" 1 "Clear" ;
VAL_ 2148826976 M2D_CMD1_PCSOperationState_32 0 "Standby" 1 "Discharge" 2 "Charge" 3 "Fault" ;
VAL_ 2148826976 M2D_CMD1_DCDCLVoffControl_32 0 "不允许低压下电" 1 "允许低压下电" ;
VAL_ 2148826977 M2D_CMD1_DCDCEnable_33 0 "Disable" 1 "Enable" ;
VAL_ 2148826977 M2D_CMD1_DCDCWrkMdSwtch_33 0 "Standby" 1 "Normal Run" 2 "Bypass" 3 "Reserved" ;
VAL_ 2148826977 M2D_CMD1_DCDCWrkMdSet_33 0 "Constant Vlotage" 1 "Constant Current" 2 "Steady Current(not greater than)" 3 "Steady Current(not less than)" ;
VAL_ 2148826977 M2D_CMD1_DCDCOutputCrrntSet_33 1276 "Null" ;
VAL_ 2148826977 M2D_CMD1_DCDCOutputVltge_Set_33 209 "Null" ;
VAL_ 2148826977 M2D_CMD1_CommunicationState_33 0 "Normal" 1 "CAN lost" ;
VAL_ 2148826977 M2D_CMD1_DCDCFaultClear_33 0 "Not Clear" 1 "Clear" ;
VAL_ 2148826977 M2D_CMD1_PCSOperationState_33 0 "Standby" 1 "Discharge" 2 "Charge" 3 "Fault" ;
VAL_ 2148826977 M2D_CMD1_DCDCLVoffControl_33 0 "不允许低压下电" 1 "允许低压下电" ;
VAL_ 2148826978 M2D_CMD1_DCDCEnable_34 0 "Disable" 1 "Enable" ;
VAL_ 2148826978 M2D_CMD1_DCDCWrkMdSwtch_34 0 "Standby" 1 "Normal Run" 2 "Bypass" 3 "Reserved" ;
VAL_ 2148826978 M2D_CMD1_DCDCWrkMdSet_34 0 "Constant Vlotage" 1 "Constant Current" 2 "Steady Current(not greater than)" 3 "Steady Current(not less than)" ;
VAL_ 2148826978 M2D_CMD1_DCDCOutputCrrntSet_34 1276 "Null" ;
VAL_ 2148826978 M2D_CMD1_DCDCOutputVltge_Set_34 209 "Null" ;
VAL_ 2148826978 M2D_CMD1_CommunicationState_34 0 "Normal" 1 "CAN lost" ;
VAL_ 2148826978 M2D_CMD1_DCDCFaultClear_34 0 "Not Clear" 1 "Clear" ;
VAL_ 2148826978 M2D_CMD1_PCSOperationState_34 0 "Standby" 1 "Discharge" 2 "Charge" 3 "Fault" ;
VAL_ 2148826978 M2D_CMD1_DCDCLVoffControl_34 0 "不允许低压下电" 1 "允许低压下电" ;
VAL_ 2148826979 M2D_CMD1_DCDCEnable_35 0 "Disable" 1 "Enable" ;
VAL_ 2148826979 M2D_CMD1_DCDCWrkMdSwtch_35 0 "Standby" 1 "Normal Run" 2 "Bypass" 3 "Reserved" ;
VAL_ 2148826979 M2D_CMD1_DCDCWrkMdSet_35 0 "Constant Vlotage" 1 "Constant Current" 2 "Steady Current(not greater than)" 3 "Steady Current(not less than)" ;
VAL_ 2148826979 M2D_CMD1_DCDCOutputCrrntSet_35 1276 "Null" ;
VAL_ 2148826979 M2D_CMD1_DCDCOutputVltge_Set_35 209 "Null" ;
VAL_ 2148826979 M2D_CMD1_CommunicationState_35 0 "Normal" 1 "CAN lost" ;
VAL_ 2148826979 M2D_CMD1_DCDCFaultClear_35 0 "Not Clear" 1 "Clear" ;
VAL_ 2148826979 M2D_CMD1_PCSOperationState_35 0 "Standby" 1 "Discharge" 2 "Charge" 3 "Fault" ;
VAL_ 2148826979 M2D_CMD1_DCDCLVoffControl_35 0 "不允许低压下电" 1 "允许低压下电" ;
VAL_ 2148826980 M2D_CMD1_DCDCEnable_36 0 "Disable" 1 "Enable" ;
VAL_ 2148826980 M2D_CMD1_DCDCWrkMdSwtch_36 0 "Standby" 1 "Normal Run" 2 "Bypass" 3 "Reserved" ;
VAL_ 2148826980 M2D_CMD1_DCDCWrkMdSet_36 0 "Constant Vlotage" 1 "Constant Current" 2 "Steady Current(not greater than)" 3 "Steady Current(not less than)" ;
VAL_ 2148826980 M2D_CMD1_DCDCOutputCrrntSet_36 1276 "Null" ;
VAL_ 2148826980 M2D_CMD1_DCDCOutputVltge_Set_36 209 "Null" ;
VAL_ 2148826980 M2D_CMD1_CommunicationState_36 0 "Normal" 1 "CAN lost" ;
VAL_ 2148826980 M2D_CMD1_DCDCFaultClear_36 0 "Not Clear" 1 "Clear" ;
VAL_ 2148826980 M2D_CMD1_PCSOperationState_36 0 "Standby" 1 "Discharge" 2 "Charge" 3 "Fault" ;
VAL_ 2148826980 M2D_CMD1_DCDCLVoffControl_36 0 "不允许低压下电" 1 "允许低压下电" ;
VAL_ 2148826981 M2D_CMD1_DCDCEnable_37 0 "Disable" 1 "Enable" ;
VAL_ 2148826981 M2D_CMD1_DCDCWrkMdSwtch_37 0 "Standby" 1 "Normal Run" 2 "Bypass" 3 "Reserved" ;
VAL_ 2148826981 M2D_CMD1_DCDCWrkMdSet_37 0 "Constant Vlotage" 1 "Constant Current" 2 "Steady Current(not greater than)" 3 "Steady Current(not less than)" ;
VAL_ 2148826981 M2D_CMD1_DCDCOutputCrrntSet_37 1276 "Null" ;
VAL_ 2148826981 M2D_CMD1_DCDCOutputVltge_Set_37 209 "Null" ;
VAL_ 2148826981 M2D_CMD1_CommunicationState_37 0 "Normal" 1 "CAN lost" ;
VAL_ 2148826981 M2D_CMD1_DCDCFaultClear_37 0 "Not Clear" 1 "Clear" ;
VAL_ 2148826981 M2D_CMD1_PCSOperationState_37 0 "Standby" 1 "Discharge" 2 "Charge" 3 "Fault" ;
VAL_ 2148826981 M2D_CMD1_DCDCLVoffControl_37 0 "不允许低压下电" 1 "允许低压下电" ;
VAL_ 2148826982 M2D_CMD1_DCDCEnable_38 0 "Disable" 1 "Enable" ;
VAL_ 2148826982 M2D_CMD1_DCDCWrkMdSwtch_38 0 "Standby" 1 "Normal Run" 2 "Bypass" 3 "Reserved" ;
VAL_ 2148826982 M2D_CMD1_DCDCWrkMdSet_38 0 "Constant Vlotage" 1 "Constant Current" 2 "Steady Current(not greater than)" 3 "Steady Current(not less than)" ;
VAL_ 2148826982 M2D_CMD1_DCDCOutputCrrntSet_38 1276 "Null" ;
VAL_ 2148826982 M2D_CMD1_DCDCOutputVltge_Set_38 209 "Null" ;
VAL_ 2148826982 M2D_CMD1_CommunicationState_38 0 "Normal" 1 "CAN lost" ;
VAL_ 2148826982 M2D_CMD1_DCDCFaultClear_38 0 "Not Clear" 1 "Clear" ;
VAL_ 2148826982 M2D_CMD1_PCSOperationState_38 0 "Standby" 1 "Discharge" 2 "Charge" 3 "Fault" ;
VAL_ 2148826982 M2D_CMD1_DCDCLVoffControl_38 0 "不允许低压下电" 1 "允许低压下电" ;
VAL_ 2148826983 M2D_CMD1_DCDCEnable_39 0 "Disable" 1 "Enable" ;
VAL_ 2148826983 M2D_CMD1_DCDCWrkMdSwtch_39 0 "Standby" 1 "Normal Run" 2 "Bypass" 3 "Reserved" ;
VAL_ 2148826983 M2D_CMD1_DCDCWrkMdSet_39 0 "Constant Vlotage" 1 "Constant Current" 2 "Steady Current(not greater than)" 3 "Steady Current(not less than)" ;
VAL_ 2148826983 M2D_CMD1_DCDCOutputCrrntSet_39 1276 "Null" ;
VAL_ 2148826983 M2D_CMD1_DCDCOutputVltge_Set_39 209 "Null" ;
VAL_ 2148826983 M2D_CMD1_CommunicationState_39 0 "Normal" 1 "CAN lost" ;
VAL_ 2148826983 M2D_CMD1_DCDCFaultClear_39 0 "Not Clear" 1 "Clear" ;
VAL_ 2148826983 M2D_CMD1_PCSOperationState_39 0 "Standby" 1 "Discharge" 2 "Charge" 3 "Fault" ;
VAL_ 2148826983 M2D_CMD1_DCDCLVoffControl_39 0 "不允许低压下电" 1 "允许低压下电" ;
VAL_ 2148826984 M2D_CMD1_DCDCEnable_40 0 "Disable" 1 "Enable" ;
VAL_ 2148826984 M2D_CMD1_DCDCWrkMdSwtch_40 0 "Standby" 1 "Normal Run" 2 "Bypass" 3 "Reserved" ;
VAL_ 2148826984 M2D_CMD1_DCDCWrkMdSet_40 0 "Constant Vlotage" 1 "Constant Current" 2 "Steady Current(not greater than)" 3 "Steady Current(not less than)" ;
VAL_ 2148826984 M2D_CMD1_DCDCOutputCrrntSet_40 1276 "Null" ;
VAL_ 2148826984 M2D_CMD1_DCDCOutputVltge_Set_40 209 "Null" ;
VAL_ 2148826984 M2D_CMD1_CommunicationState_40 0 "Normal" 1 "CAN lost" ;
VAL_ 2148826984 M2D_CMD1_DCDCFaultClear_40 0 "Not Clear" 1 "Clear" ;
VAL_ 2148826984 M2D_CMD1_PCSOperationState_40 0 "Standby" 1 "Discharge" 2 "Charge" 3 "Fault" ;
VAL_ 2148826984 M2D_CMD1_DCDCLVoffControl_40 0 "不允许低压下电" 1 "允许低压下电" ;
VAL_ 2148826985 M2D_CMD1_DCDCEnable_41 0 "Disable" 1 "Enable" ;
VAL_ 2148826985 M2D_CMD1_DCDCWrkMdSwtch_41 0 "Standby" 1 "Normal Run" 2 "Bypass" 3 "Reserved" ;
VAL_ 2148826985 M2D_CMD1_DCDCWrkMdSet_41 0 "Constant Vlotage" 1 "Constant Current" 2 "Steady Current(not greater than)" 3 "Steady Current(not less than)" ;
VAL_ 2148826985 M2D_CMD1_DCDCOutputCrrntSet_41 1276 "Null" ;
VAL_ 2148826985 M2D_CMD1_DCDCOutputVltge_Set_41 209 "Null" ;
VAL_ 2148826985 M2D_CMD1_CommunicationState_41 0 "Normal" 1 "CAN lost" ;
VAL_ 2148826985 M2D_CMD1_DCDCFaultClear_41 0 "Not Clear" 1 "Clear" ;
VAL_ 2148826985 M2D_CMD1_PCSOperationState_41 0 "Standby" 1 "Discharge" 2 "Charge" 3 "Fault" ;
VAL_ 2148826985 M2D_CMD1_DCDCLVoffControl_41 0 "不允许低压下电" 1 "允许低压下电" ;
VAL_ 2148826986 M2D_CMD1_DCDCEnable_42 0 "Disable" 1 "Enable" ;
VAL_ 2148826986 M2D_CMD1_DCDCWrkMdSwtch_42 0 "Standby" 1 "Normal Run" 2 "Bypass" 3 "Reserved" ;
VAL_ 2148826986 M2D_CMD1_DCDCWrkMdSet_42 0 "Constant Vlotage" 1 "Constant Current" 2 "Steady Current(not greater than)" 3 "Steady Current(not less than)" ;
VAL_ 2148826986 M2D_CMD1_DCDCOutputCrrntSet_42 1276 "Null" ;
VAL_ 2148826986 M2D_CMD1_DCDCOutputVltge_Set_42 209 "Null" ;
VAL_ 2148826986 M2D_CMD1_CommunicationState_42 0 "Normal" 1 "CAN lost" ;
VAL_ 2148826986 M2D_CMD1_DCDCFaultClear_42 0 "Not Clear" 1 "Clear" ;
VAL_ 2148826986 M2D_CMD1_PCSOperationState_42 0 "Standby" 1 "Discharge" 2 "Charge" 3 "Fault" ;
VAL_ 2148826986 M2D_CMD1_DCDCLVoffControl_42 0 "不允许低压下电" 1 "允许低压下电" ;
VAL_ 2148826987 M2D_CMD1_DCDCEnable_43 0 "Disable" 1 "Enable" ;
VAL_ 2148826987 M2D_CMD1_DCDCWrkMdSwtch_43 0 "Standby" 1 "Normal Run" 2 "Bypass" 3 "Reserved" ;
VAL_ 2148826987 M2D_CMD1_DCDCWrkMdSet_43 0 "Constant Vlotage" 1 "Constant Current" 2 "Steady Current(not greater than)" 3 "Steady Current(not less than)" ;
VAL_ 2148826987 M2D_CMD1_DCDCOutputCrrntSet_43 1276 "Null" ;
VAL_ 2148826987 M2D_CMD1_DCDCOutputVltge_Set_43 209 "Null" ;
VAL_ 2148826987 M2D_CMD1_CommunicationState_43 0 "Normal" 1 "CAN lost" ;
VAL_ 2148826987 M2D_CMD1_DCDCFaultClear_43 0 "Not Clear" 1 "Clear" ;
VAL_ 2148826987 M2D_CMD1_PCSOperationState_43 0 "Standby" 1 "Discharge" 2 "Charge" 3 "Fault" ;
VAL_ 2148826987 M2D_CMD1_DCDCLVoffControl_43 0 "不允许低压下电" 1 "允许低压下电" ;
VAL_ 2148826988 M2D_CMD1_DCDCEnable_44 0 "Disable" 1 "Enable" ;
VAL_ 2148826988 M2D_CMD1_DCDCWrkMdSwtch_44 0 "Standby" 1 "Normal Run" 2 "Bypass" 3 "Reserved" ;
VAL_ 2148826988 M2D_CMD1_DCDCWrkMdSet_44 0 "Constant Vlotage" 1 "Constant Current" 2 "Steady Current(not greater than)" 3 "Steady Current(not less than)" ;
VAL_ 2148826988 M2D_CMD1_DCDCOutputCrrntSet_44 1276 "Null" ;
VAL_ 2148826988 M2D_CMD1_DCDCOutputVltge_Set_44 209 "Null" ;
VAL_ 2148826988 M2D_CMD1_CommunicationState_44 0 "Normal" 1 "CAN lost" ;
VAL_ 2148826988 M2D_CMD1_DCDCFaultClear_44 0 "Not Clear" 1 "Clear" ;
VAL_ 2148826988 M2D_CMD1_PCSOperationState_44 0 "Standby" 1 "Discharge" 2 "Charge" 3 "Fault" ;
VAL_ 2148826988 M2D_CMD1_DCDCLVoffControl_44 0 "不允许低压下电" 1 "允许低压下电" ;
VAL_ 2148826989 M2D_CMD1_DCDCEnable_45 0 "Disable" 1 "Enable" ;
VAL_ 2148826989 M2D_CMD1_DCDCWrkMdSwtch_45 0 "Standby" 1 "Normal Run" 2 "Bypass" 3 "Reserved" ;
VAL_ 2148826989 M2D_CMD1_DCDCWrkMdSet_45 0 "Constant Vlotage" 1 "Constant Current" 2 "Steady Current(not greater than)" 3 "Steady Current(not less than)" ;
VAL_ 2148826989 M2D_CMD1_DCDCOutputCrrntSet_45 1276 "Null" ;
VAL_ 2148826989 M2D_CMD1_DCDCOutputVltge_Set_45 209 "Null" ;
VAL_ 2148826989 M2D_CMD1_CommunicationState_45 0 "Normal" 1 "CAN lost" ;
VAL_ 2148826989 M2D_CMD1_DCDCFaultClear_45 0 "Not Clear" 1 "Clear" ;
VAL_ 2148826989 M2D_CMD1_PCSOperationState_45 0 "Standby" 1 "Discharge" 2 "Charge" 3 "Fault" ;
VAL_ 2148826989 M2D_CMD1_DCDCLVoffControl_45 0 "不允许低压下电" 1 "允许低压下电" ;
VAL_ 2148826990 M2D_CMD1_DCDCEnable_46 0 "Disable" 1 "Enable" ;
VAL_ 2148826990 M2D_CMD1_DCDCWrkMdSwtch_46 0 "Standby" 1 "Normal Run" 2 "Bypass" 3 "Reserved" ;
VAL_ 2148826990 M2D_CMD1_DCDCWrkMdSet_46 0 "Constant Vlotage" 1 "Constant Current" 2 "Steady Current(not greater than)" 3 "Steady Current(not less than)" ;
VAL_ 2148826990 M2D_CMD1_DCDCOutputCrrntSet_46 1276 "Null" ;
VAL_ 2148826990 M2D_CMD1_DCDCOutputVltge_Set_46 209 "Null" ;
VAL_ 2148826990 M2D_CMD1_CommunicationState_46 0 "Normal" 1 "CAN lost" ;
VAL_ 2148826990 M2D_CMD1_DCDCFaultClear_46 0 "Not Clear" 1 "Clear" ;
VAL_ 2148826990 M2D_CMD1_PCSOperationState_46 0 "Standby" 1 "Discharge" 2 "Charge" 3 "Fault" ;
VAL_ 2148826990 M2D_CMD1_DCDCLVoffControl_46 0 "不允许低压下电" 1 "允许低压下电" ;
VAL_ 2148826991 M2D_CMD1_DCDCEnable_47 0 "Disable" 1 "Enable" ;
VAL_ 2148826991 M2D_CMD1_DCDCWrkMdSwtch_47 0 "Standby" 1 "Normal Run" 2 "Bypass" 3 "Reserved" ;
VAL_ 2148826991 M2D_CMD1_DCDCWrkMdSet_47 0 "Constant Vlotage" 1 "Constant Current" 2 "Steady Current(not greater than)" 3 "Steady Current(not less than)" ;
VAL_ 2148826991 M2D_CMD1_DCDCOutputCrrntSet_47 1276 "Null" ;
VAL_ 2148826991 M2D_CMD1_DCDCOutputVltge_Set_47 209 "Null" ;
VAL_ 2148826991 M2D_CMD1_CommunicationState_47 0 "Normal" 1 "CAN lost" ;
VAL_ 2148826991 M2D_CMD1_DCDCFaultClear_47 0 "Not Clear" 1 "Clear" ;
VAL_ 2148826991 M2D_CMD1_PCSOperationState_47 0 "Standby" 1 "Discharge" 2 "Charge" 3 "Fault" ;
VAL_ 2148826991 M2D_CMD1_DCDCLVoffControl_47 0 "不允许低压下电" 1 "允许低压下电" ;
VAL_ 2148826992 M2D_CMD1_DCDCEnable_48 0 "Disable" 1 "Enable" ;
VAL_ 2148826992 M2D_CMD1_DCDCWrkMdSwtch_48 0 "Standby" 1 "Normal Run" 2 "Bypass" 3 "Reserved" ;
VAL_ 2148826992 M2D_CMD1_DCDCWrkMdSet_48 0 "Constant Vlotage" 1 "Constant Current" 2 "Steady Current(not greater than)" 3 "Steady Current(not less than)" ;
VAL_ 2148826992 M2D_CMD1_DCDCOutputCrrntSet_48 1276 "Null" ;
VAL_ 2148826992 M2D_CMD1_DCDCOutputVltge_Set_48 209 "Null" ;
VAL_ 2148826992 M2D_CMD1_CommunicationState_48 0 "Normal" 1 "CAN lost" ;
VAL_ 2148826992 M2D_CMD1_DCDCFaultClear_48 0 "Not Clear" 1 "Clear" ;
VAL_ 2148826992 M2D_CMD1_PCSOperationState_48 0 "Standby" 1 "Discharge" 2 "Charge" 3 "Fault" ;
VAL_ 2148826992 M2D_CMD1_DCDCLVoffControl_48 0 "不允许低压下电" 1 "允许低压下电" ;
VAL_ 2148826993 M2D_CMD1_DCDCEnable_49 0 "Disable" 1 "Enable" ;
VAL_ 2148826993 M2D_CMD1_DCDCWrkMdSwtch_49 0 "Standby" 1 "Normal Run" 2 "Bypass" 3 "Reserved" ;
VAL_ 2148826993 M2D_CMD1_DCDCWrkMdSet_49 0 "Constant Vlotage" 1 "Constant Current" 2 "Steady Current(not greater than)" 3 "Steady Current(not less than)" ;
VAL_ 2148826993 M2D_CMD1_DCDCOutputCrrntSet_49 1276 "Null" ;
VAL_ 2148826993 M2D_CMD1_DCDCOutputVltge_Set_49 209 "Null" ;
VAL_ 2148826993 M2D_CMD1_CommunicationState_49 0 "Normal" 1 "CAN lost" ;
VAL_ 2148826993 M2D_CMD1_DCDCFaultClear_49 0 "Not Clear" 1 "Clear" ;
VAL_ 2148826993 M2D_CMD1_PCSOperationState_49 0 "Standby" 1 "Discharge" 2 "Charge" 3 "Fault" ;
VAL_ 2148826993 M2D_CMD1_DCDCLVoffControl_49 0 "不允许低压下电" 1 "允许低压下电" ;
VAL_ 2148826994 M2D_CMD1_DCDCEnable_50 0 "Disable" 1 "Enable" ;
VAL_ 2148826994 M2D_CMD1_DCDCWrkMdSwtch_50 0 "Standby" 1 "Normal Run" 2 "Bypass" 3 "Reserved" ;
VAL_ 2148826994 M2D_CMD1_DCDCWrkMdSet_50 0 "Constant Vlotage" 1 "Constant Current" 2 "Steady Current(not greater than)" 3 "Steady Current(not less than)" ;
VAL_ 2148826994 M2D_CMD1_DCDCOutputCrrntSet_50 1276 "Null" ;
VAL_ 2148826994 M2D_CMD1_DCDCOutputVltge_Set_50 209 "Null" ;
VAL_ 2148826994 M2D_CMD1_CommunicationState_50 0 "Normal" 1 "CAN lost" ;
VAL_ 2148826994 M2D_CMD1_DCDCFaultClear_50 0 "Not Clear" 1 "Clear" ;
VAL_ 2148826994 M2D_CMD1_PCSOperationState_50 0 "Standby" 1 "Discharge" 2 "Charge" 3 "Fault" ;
VAL_ 2148826994 M2D_CMD1_DCDCLVoffControl_50 0 "不允许低压下电" 1 "允许低压下电" ;
VAL_ 2148826995 M2D_CMD1_DCDCEnable_51 0 "Disable" 1 "Enable" ;
VAL_ 2148826995 M2D_CMD1_DCDCWrkMdSwtch_51 0 "Standby" 1 "Normal Run" 2 "Bypass" 3 "Reserved" ;
VAL_ 2148826995 M2D_CMD1_DCDCWrkMdSet_51 0 "Constant Vlotage" 1 "Constant Current" 2 "Steady Current(not greater than)" 3 "Steady Current(not less than)" ;
VAL_ 2148826995 M2D_CMD1_DCDCOutputCrrntSet_51 1276 "Null" ;
VAL_ 2148826995 M2D_CMD1_DCDCOutputVltge_Set_51 209 "Null" ;
VAL_ 2148826995 M2D_CMD1_CommunicationState_51 0 "Normal" 1 "CAN lost" ;
VAL_ 2148826995 M2D_CMD1_DCDCFaultClear_51 0 "Not Clear" 1 "Clear" ;
VAL_ 2148826995 M2D_CMD1_PCSOperationState_51 0 "Standby" 1 "Discharge" 2 "Charge" 3 "Fault" ;
VAL_ 2148826995 M2D_CMD1_DCDCLVoffControl_51 0 "不允许低压下电" 1 "允许低压下电" ;
VAL_ 2148826996 M2D_CMD1_DCDCEnable_52 0 "Disable" 1 "Enable" ;
VAL_ 2148826996 M2D_CMD1_DCDCWrkMdSwtch_52 0 "Standby" 1 "Normal Run" 2 "Bypass" 3 "Reserved" ;
VAL_ 2148826996 M2D_CMD1_DCDCWrkMdSet_52 0 "Constant Vlotage" 1 "Constant Current" 2 "Steady Current(not greater than)" 3 "Steady Current(not less than)" ;
VAL_ 2148826996 M2D_CMD1_DCDCOutputCrrntSet_52 1276 "Null" ;
VAL_ 2148826996 M2D_CMD1_DCDCOutputVltge_Set_52 209 "Null" ;
VAL_ 2148826996 M2D_CMD1_CommunicationState_52 0 "Normal" 1 "CAN lost" ;
VAL_ 2148826996 M2D_CMD1_DCDCFaultClear_52 0 "Not Clear" 1 "Clear" ;
VAL_ 2148826996 M2D_CMD1_PCSOperationState_52 0 "Standby" 1 "Discharge" 2 "Charge" 3 "Fault" ;
VAL_ 2148826996 M2D_CMD1_DCDCLVoffControl_52 0 "不允许低压下电" 1 "允许低压下电" ;
VAL_ 2148826997 M2D_CMD1_DCDCEnable_53 0 "Disable" 1 "Enable" ;
VAL_ 2148826997 M2D_CMD1_DCDCWrkMdSwtch_53 0 "Standby" 1 "Normal Run" 2 "Bypass" 3 "Reserved" ;
VAL_ 2148826997 M2D_CMD1_DCDCWrkMdSet_53 0 "Constant Vlotage" 1 "Constant Current" 2 "Steady Current(not greater than)" 3 "Steady Current(not less than)" ;
VAL_ 2148826997 M2D_CMD1_DCDCOutputCrrntSet_53 1276 "Null" ;
VAL_ 2148826997 M2D_CMD1_DCDCOutputVltge_Set_53 209 "Null" ;
VAL_ 2148826997 M2D_CMD1_CommunicationState_53 0 "Normal" 1 "CAN lost" ;
VAL_ 2148826997 M2D_CMD1_DCDCFaultClear_53 0 "Not Clear" 1 "Clear" ;
VAL_ 2148826997 M2D_CMD1_PCSOperationState_53 0 "Standby" 1 "Discharge" 2 "Charge" 3 "Fault" ;
VAL_ 2148826997 M2D_CMD1_DCDCLVoffControl_53 0 "不允许低压下电" 1 "允许低压下电" ;
VAL_ 2148826998 M2D_CMD1_DCDCEnable_54 0 "Disable" 1 "Enable" ;
VAL_ 2148826998 M2D_CMD1_DCDCWrkMdSwtch_54 0 "Standby" 1 "Normal Run" 2 "Bypass" 3 "Reserved" ;
VAL_ 2148826998 M2D_CMD1_DCDCWrkMdSet_54 0 "Constant Vlotage" 1 "Constant Current" 2 "Steady Current(not greater than)" 3 "Steady Current(not less than)" ;
VAL_ 2148826998 M2D_CMD1_DCDCOutputCrrntSet_54 1276 "Null" ;
VAL_ 2148826998 M2D_CMD1_DCDCOutputVltge_Set_54 209 "Null" ;
VAL_ 2148826998 M2D_CMD1_CommunicationState_54 0 "Normal" 1 "CAN lost" ;
VAL_ 2148826998 M2D_CMD1_DCDCFaultClear_54 0 "Not Clear" 1 "Clear" ;
VAL_ 2148826998 M2D_CMD1_PCSOperationState_54 0 "Standby" 1 "Discharge" 2 "Charge" 3 "Fault" ;
VAL_ 2148826998 M2D_CMD1_DCDCLVoffControl_54 0 "不允许低压下电" 1 "允许低压下电" ;
VAL_ 2148826999 M2D_CMD1_DCDCEnable_55 0 "Disable" 1 "Enable" ;
VAL_ 2148826999 M2D_CMD1_DCDCWrkMdSwtch_55 0 "Standby" 1 "Normal Run" 2 "Bypass" 3 "Reserved" ;
VAL_ 2148826999 M2D_CMD1_DCDCWrkMdSet_55 0 "Constant Vlotage" 1 "Constant Current" 2 "Steady Current(not greater than)" 3 "Steady Current(not less than)" ;
VAL_ 2148826999 M2D_CMD1_DCDCOutputCrrntSet_55 1276 "Null" ;
VAL_ 2148826999 M2D_CMD1_DCDCOutputVltge_Set_55 209 "Null" ;
VAL_ 2148826999 M2D_CMD1_CommunicationState_55 0 "Normal" 1 "CAN lost" ;
VAL_ 2148826999 M2D_CMD1_DCDCFaultClear_55 0 "Not Clear" 1 "Clear" ;
VAL_ 2148826999 M2D_CMD1_PCSOperationState_55 0 "Standby" 1 "Discharge" 2 "Charge" 3 "Fault" ;
VAL_ 2148826999 M2D_CMD1_DCDCLVoffControl_55 0 "不允许低压下电" 1 "允许低压下电" ;
VAL_ 2148827000 M2D_CMD1_DCDCEnable_56 0 "Disable" 1 "Enable" ;
VAL_ 2148827000 M2D_CMD1_DCDCWrkMdSwtch_56 0 "Standby" 1 "Normal Run" 2 "Bypass" 3 "Reserved" ;
VAL_ 2148827000 M2D_CMD1_DCDCWrkMdSet_56 0 "Constant Vlotage" 1 "Constant Current" 2 "Steady Current(not greater than)" 3 "Steady Current(not less than)" ;
VAL_ 2148827000 M2D_CMD1_DCDCOutputCrrntSet_56 1276 "Null" ;
VAL_ 2148827000 M2D_CMD1_DCDCOutputVltge_Set_56 209 "Null" ;
VAL_ 2148827000 M2D_CMD1_CommunicationState_56 0 "Normal" 1 "CAN lost" ;
VAL_ 2148827000 M2D_CMD1_DCDCFaultClear_56 0 "Not Clear" 1 "Clear" ;
VAL_ 2148827000 M2D_CMD1_PCSOperationState_56 0 "Standby" 1 "Discharge" 2 "Charge" 3 "Fault" ;
VAL_ 2148827000 M2D_CMD1_DCDCLVoffControl_56 0 "不允许低压下电" 1 "允许低压下电" ;
VAL_ 2148827001 M2D_CMD1_DCDCEnable_57 0 "Disable" 1 "Enable" ;
VAL_ 2148827001 M2D_CMD1_DCDCWrkMdSwtch_57 0 "Standby" 1 "Normal Run" 2 "Bypass" 3 "Reserved" ;
VAL_ 2148827001 M2D_CMD1_DCDCWrkMdSet_57 0 "Constant Vlotage" 1 "Constant Current" 2 "Steady Current(not greater than)" 3 "Steady Current(not less than)" ;
VAL_ 2148827001 M2D_CMD1_DCDCOutputCrrntSet_57 1276 "Null" ;
VAL_ 2148827001 M2D_CMD1_DCDCOutputVltge_Set_57 209 "Null" ;
VAL_ 2148827001 M2D_CMD1_CommunicationState_57 0 "Normal" 1 "CAN lost" ;
VAL_ 2148827001 M2D_CMD1_DCDCFaultClear_57 0 "Not Clear" 1 "Clear" ;
VAL_ 2148827001 M2D_CMD1_PCSOperationState_57 0 "Standby" 1 "Discharge" 2 "Charge" 3 "Fault" ;
VAL_ 2148827001 M2D_CMD1_DCDCLVoffControl_57 0 "不允许低压下电" 1 "允许低压下电" ;
VAL_ 2148827002 M2D_CMD1_DCDCEnable_58 0 "Disable" 1 "Enable" ;
VAL_ 2148827002 M2D_CMD1_DCDCWrkMdSwtch_58 0 "Standby" 1 "Normal Run" 2 "Bypass" 3 "Reserved" ;
VAL_ 2148827002 M2D_CMD1_DCDCWrkMdSet_58 0 "Constant Vlotage" 1 "Constant Current" 2 "Steady Current(not greater than)" 3 "Steady Current(not less than)" ;
VAL_ 2148827002 M2D_CMD1_DCDCOutputCrrntSet_58 1276 "Null" ;
VAL_ 2148827002 M2D_CMD1_DCDCOutputVltge_Set_58 209 "Null" ;
VAL_ 2148827002 M2D_CMD1_CommunicationState_58 0 "Normal" 1 "CAN lost" ;
VAL_ 2148827002 M2D_CMD1_DCDCFaultClear_58 0 "Not Clear" 1 "Clear" ;
VAL_ 2148827002 M2D_CMD1_PCSOperationState_58 0 "Standby" 1 "Discharge" 2 "Charge" 3 "Fault" ;
VAL_ 2148827002 M2D_CMD1_DCDCLVoffControl_58 0 "不允许低压下电" 1 "允许低压下电" ;
VAL_ 2148827003 M2D_CMD1_DCDCEnable_59 0 "Disable" 1 "Enable" ;
VAL_ 2148827003 M2D_CMD1_DCDCWrkMdSwtch_59 0 "Standby" 1 "Normal Run" 2 "Bypass" 3 "Reserved" ;
VAL_ 2148827003 M2D_CMD1_DCDCWrkMdSet_59 0 "Constant Vlotage" 1 "Constant Current" 2 "Steady Current(not greater than)" 3 "Steady Current(not less than)" ;
VAL_ 2148827003 M2D_CMD1_DCDCOutputCrrntSet_59 1276 "Null" ;
VAL_ 2148827003 M2D_CMD1_DCDCOutputVltge_Set_59 209 "Null" ;
VAL_ 2148827003 M2D_CMD1_CommunicationState_59 0 "Normal" 1 "CAN lost" ;
VAL_ 2148827003 M2D_CMD1_DCDCFaultClear_59 0 "Not Clear" 1 "Clear" ;
VAL_ 2148827003 M2D_CMD1_PCSOperationState_59 0 "Standby" 1 "Discharge" 2 "Charge" 3 "Fault" ;
VAL_ 2148827003 M2D_CMD1_DCDCLVoffControl_59 0 "不允许低压下电" 1 "允许低压下电" ;
VAL_ 2148827004 M2D_CMD1_DCDCEnable_60 0 "Disable" 1 "Enable" ;
VAL_ 2148827004 M2D_CMD1_DCDCWrkMdSwtch_60 0 "Standby" 1 "Normal Run" 2 "Bypass" 3 "Reserved" ;
VAL_ 2148827004 M2D_CMD1_DCDCWrkMdSet_60 0 "Constant Vlotage" 1 "Constant Current" 2 "Steady Current(not greater than)" 3 "Steady Current(not less than)" ;
VAL_ 2148827004 M2D_CMD1_DCDCOutputCrrntSet_60 1276 "Null" ;
VAL_ 2148827004 M2D_CMD1_DCDCOutputVltge_Set_60 209 "Null" ;
VAL_ 2148827004 M2D_CMD1_CommunicationState_60 0 "Normal" 1 "CAN lost" ;
VAL_ 2148827004 M2D_CMD1_DCDCFaultClear_60 0 "Not Clear" 1 "Clear" ;
VAL_ 2148827004 M2D_CMD1_PCSOperationState_60 0 "Standby" 1 "Discharge" 2 "Charge" 3 "Fault" ;
VAL_ 2148827004 M2D_CMD1_DCDCLVoffControl_60 0 "不允许低压下电" 1 "允许低压下电" ;
VAL_ 2148827005 M2D_CMD1_DCDCEnable_61 0 "Disable" 1 "Enable" ;
VAL_ 2148827005 M2D_CMD1_DCDCWrkMdSwtch_61 0 "Standby" 1 "Normal Run" 2 "Bypass" 3 "Reserved" ;
VAL_ 2148827005 M2D_CMD1_DCDCWrkMdSet_61 0 "Constant Vlotage" 1 "Constant Current" 2 "Steady Current(not greater than)" 3 "Steady Current(not less than)" ;
VAL_ 2148827005 M2D_CMD1_DCDCOutputCrrntSet_61 1276 "Null" ;
VAL_ 2148827005 M2D_CMD1_DCDCOutputVltge_Set_61 209 "Null" ;
VAL_ 2148827005 M2D_CMD1_CommunicationState_61 0 "Normal" 1 "CAN lost" ;
VAL_ 2148827005 M2D_CMD1_DCDCFaultClear_61 0 "Not Clear" 1 "Clear" ;
VAL_ 2148827005 M2D_CMD1_PCSOperationState_61 0 "Standby" 1 "Discharge" 2 "Charge" 3 "Fault" ;
VAL_ 2148827005 M2D_CMD1_DCDCLVoffControl_61 0 "不允许低压下电" 1 "允许低压下电" ;
VAL_ 2148827006 M2D_CMD1_DCDCEnable_62 0 "Disable" 1 "Enable" ;
VAL_ 2148827006 M2D_CMD1_DCDCWrkMdSwtch_62 0 "Standby" 1 "Normal Run" 2 "Bypass" 3 "Reserved" ;
VAL_ 2148827006 M2D_CMD1_DCDCWrkMdSet_62 0 "Constant Vlotage" 1 "Constant Current" 2 "Steady Current(not greater than)" 3 "Steady Current(not less than)" ;
VAL_ 2148827006 M2D_CMD1_DCDCOutputCrrntSet_62 1276 "Null" ;
VAL_ 2148827006 M2D_CMD1_DCDCOutputVltge_Set_62 209 "Null" ;
VAL_ 2148827006 M2D_CMD1_CommunicationState_62 0 "Normal" 1 "CAN lost" ;
VAL_ 2148827006 M2D_CMD1_DCDCFaultClear_62 0 "Not Clear" 1 "Clear" ;
VAL_ 2148827006 M2D_CMD1_PCSOperationState_62 0 "Standby" 1 "Discharge" 2 "Charge" 3 "Fault" ;
VAL_ 2148827006 M2D_CMD1_DCDCLVoffControl_62 0 "不允许低压下电" 1 "允许低压下电" ;
VAL_ 2148827007 M2D_CMD1_DCDCEnable_63 0 "Disable" 1 "Enable" ;
VAL_ 2148827007 M2D_CMD1_DCDCWrkMdSwtch_63 0 "Standby" 1 "Normal Run" 2 "Bypass" 3 "Reserved" ;
VAL_ 2148827007 M2D_CMD1_DCDCWrkMdSet_63 0 "Constant Vlotage" 1 "Constant Current" 2 "Steady Current(not greater than)" 3 "Steady Current(not less than)" ;
VAL_ 2148827007 M2D_CMD1_DCDCOutputCrrntSet_63 1276 "Null" ;
VAL_ 2148827007 M2D_CMD1_DCDCOutputVltge_Set_63 209 "Null" ;
VAL_ 2148827007 M2D_CMD1_CommunicationState_63 0 "Normal" 1 "CAN lost" ;
VAL_ 2148827007 M2D_CMD1_DCDCFaultClear_63 0 "Not Clear" 1 "Clear" ;
VAL_ 2148827007 M2D_CMD1_PCSOperationState_63 0 "Standby" 1 "Discharge" 2 "Charge" 3 "Fault" ;
VAL_ 2148827007 M2D_CMD1_DCDCLVoffControl_63 0 "不允许低压下电" 1 "允许低压下电" ;
VAL_ 2148892481 M2D_IDX_CMD_Type_01 0 "Invalid" 2 "Code Index" 5 "Confirm Index" 6 "Exit Code" 7 "Start Code" 8 "Code Failed" 9 "Code Success" 10 "Invalid" 255 "Null" ;
VAL_ 2148892481 M2D_IDX_DCDC_Index_01 0 "Initial Index" 1 "Index 1" 2 "Index 2" 3 "Index 3" 4 "Index 4" 5 "Index 5" 6 "Index 6" 7 "Index 7" 8 "Index 8" 9 "Index 9" 10 "Index 10" 11 "Index 11" 12 "Index 12" 13 "Index 13" 14 "Index 14" 15 "Index 15" 255 "Null" ;
VAL_ 2148892482 M2D_IDX_CMD_Type_02 0 "Invalid" 2 "Code Index" 5 "Confirm Index" 6 "Exit Code" 7 "Start Code" 8 "Code Failed" 9 "Code Success" 10 "Invalid" 255 "Null" ;
VAL_ 2148892482 M2D_IDX_DCDC_Index_02 0 "Initial Index" 1 "Index 1" 2 "Index 2" 3 "Index 3" 4 "Index 4" 5 "Index 5" 6 "Index 6" 7 "Index 7" 8 "Index 8" 9 "Index 9" 10 "Index 10" 11 "Index 11" 12 "Index 12" 13 "Index 13" 14 "Index 14" 15 "Index 15" 255 "Null" ;
VAL_ 2148892483 M2D_IDX_CMD_Type_03 0 "Invalid" 2 "Code Index" 5 "Confirm Index" 6 "Exit Code" 7 "Start Code" 8 "Code Failed" 9 "Code Success" 10 "Invalid" 255 "Null" ;
VAL_ 2148892483 M2D_IDX_DCDC_Index_03 0 "Initial Index" 1 "Index 1" 2 "Index 2" 3 "Index 3" 4 "Index 4" 5 "Index 5" 6 "Index 6" 7 "Index 7" 8 "Index 8" 9 "Index 9" 10 "Index 10" 11 "Index 11" 12 "Index 12" 13 "Index 13" 14 "Index 14" 15 "Index 15" 255 "Null" ;
VAL_ 2148892484 M2D_IDX_CMD_Type_04 0 "Invalid" 2 "Code Index" 5 "Confirm Index" 6 "Exit Code" 7 "Start Code" 8 "Code Failed" 9 "Code Success" 10 "Invalid" 255 "Null" ;
VAL_ 2148892484 M2D_IDX_DCDC_Index_04 0 "Initial Index" 1 "Index 1" 2 "Index 2" 3 "Index 3" 4 "Index 4" 5 "Index 5" 6 "Index 6" 7 "Index 7" 8 "Index 8" 9 "Index 9" 10 "Index 10" 11 "Index 11" 12 "Index 12" 13 "Index 13" 14 "Index 14" 15 "Index 15" 255 "Null" ;
VAL_ 2148892485 M2D_IDX_CMD_Type_05 0 "Invalid" 2 "Code Index" 5 "Confirm Index" 6 "Exit Code" 7 "Start Code" 8 "Code Failed" 9 "Code Success" 10 "Invalid" 255 "Null" ;
VAL_ 2148892485 M2D_IDX_DCDC_Index_05 0 "Initial Index" 1 "Index 1" 2 "Index 2" 3 "Index 3" 4 "Index 4" 5 "Index 5" 6 "Index 6" 7 "Index 7" 8 "Index 8" 9 "Index 9" 10 "Index 10" 11 "Index 11" 12 "Index 12" 13 "Index 13" 14 "Index 14" 15 "Index 15" 255 "Null" ;
VAL_ 2148892486 M2D_IDX_CMD_Type_06 0 "Invalid" 2 "Code Index" 5 "Confirm Index" 6 "Exit Code" 7 "Start Code" 8 "Code Failed" 9 "Code Success" 10 "Invalid" 255 "Null" ;
VAL_ 2148892486 M2D_IDX_DCDC_Index_06 0 "Initial Index" 1 "Index 1" 2 "Index 2" 3 "Index 3" 4 "Index 4" 5 "Index 5" 6 "Index 6" 7 "Index 7" 8 "Index 8" 9 "Index 9" 10 "Index 10" 11 "Index 11" 12 "Index 12" 13 "Index 13" 14 "Index 14" 15 "Index 15" 255 "Null" ;
VAL_ 2148892487 M2D_IDX_CMD_Type_07 0 "Invalid" 2 "Code Index" 5 "Confirm Index" 6 "Exit Code" 7 "Start Code" 8 "Code Failed" 9 "Code Success" 10 "Invalid" 255 "Null" ;
VAL_ 2148892487 M2D_IDX_DCDC_Index_07 0 "Initial Index" 1 "Index 1" 2 "Index 2" 3 "Index 3" 4 "Index 4" 5 "Index 5" 6 "Index 6" 7 "Index 7" 8 "Index 8" 9 "Index 9" 10 "Index 10" 11 "Index 11" 12 "Index 12" 13 "Index 13" 14 "Index 14" 15 "Index 15" 255 "Null" ;
VAL_ 2148892488 M2D_IDX_CMD_Type_08 0 "Invalid" 2 "Code Index" 5 "Confirm Index" 6 "Exit Code" 7 "Start Code" 8 "Code Failed" 9 "Code Success" 10 "Invalid" 255 "Null" ;
VAL_ 2148892488 M2D_IDX_DCDC_Index_08 0 "Initial Index" 1 "Index 1" 2 "Index 2" 3 "Index 3" 4 "Index 4" 5 "Index 5" 6 "Index 6" 7 "Index 7" 8 "Index 8" 9 "Index 9" 10 "Index 10" 11 "Index 11" 12 "Index 12" 13 "Index 13" 14 "Index 14" 15 "Index 15" 255 "Null" ;
VAL_ 2148892489 M2D_IDX_CMD_Type_09 0 "Invalid" 2 "Code Index" 5 "Confirm Index" 6 "Exit Code" 7 "Start Code" 8 "Code Failed" 9 "Code Success" 10 "Invalid" 255 "Null" ;
VAL_ 2148892489 M2D_IDX_DCDC_Index_09 0 "Initial Index" 1 "Index 1" 2 "Index 2" 3 "Index 3" 4 "Index 4" 5 "Index 5" 6 "Index 6" 7 "Index 7" 8 "Index 8" 9 "Index 9" 10 "Index 10" 11 "Index 11" 12 "Index 12" 13 "Index 13" 14 "Index 14" 15 "Index 15" 255 "Null" ;
VAL_ 2148892490 M2D_IDX_CMD_Type_10 0 "Invalid" 2 "Code Index" 5 "Confirm Index" 6 "Exit Code" 7 "Start Code" 8 "Code Failed" 9 "Code Success" 10 "Invalid" 255 "Null" ;
VAL_ 2148892490 M2D_IDX_DCDC_Index_10 0 "Initial Index" 1 "Index 1" 2 "Index 2" 3 "Index 3" 4 "Index 4" 5 "Index 5" 6 "Index 6" 7 "Index 7" 8 "Index 8" 9 "Index 9" 10 "Index 10" 11 "Index 11" 12 "Index 12" 13 "Index 13" 14 "Index 14" 15 "Index 15" 255 "Null" ;
VAL_ 2148892491 M2D_IDX_CMD_Type_11 0 "Invalid" 2 "Code Index" 5 "Confirm Index" 6 "Exit Code" 7 "Start Code" 8 "Code Failed" 9 "Code Success" 10 "Invalid" 255 "Null" ;
VAL_ 2148892491 M2D_IDX_DCDC_Index_11 0 "Initial Index" 1 "Index 1" 2 "Index 2" 3 "Index 3" 4 "Index 4" 5 "Index 5" 6 "Index 6" 7 "Index 7" 8 "Index 8" 9 "Index 9" 10 "Index 10" 11 "Index 11" 12 "Index 12" 13 "Index 13" 14 "Index 14" 15 "Index 15" 255 "Null" ;
VAL_ 2148892492 M2D_IDX_CMD_Type_12 0 "Invalid" 2 "Code Index" 5 "Confirm Index" 6 "Exit Code" 7 "Start Code" 8 "Code Failed" 9 "Code Success" 10 "Invalid" 255 "Null" ;
VAL_ 2148892492 M2D_IDX_DCDC_Index_12 0 "Initial Index" 1 "Index 1" 2 "Index 2" 3 "Index 3" 4 "Index 4" 5 "Index 5" 6 "Index 6" 7 "Index 7" 8 "Index 8" 9 "Index 9" 10 "Index 10" 11 "Index 11" 12 "Index 12" 13 "Index 13" 14 "Index 14" 15 "Index 15" 255 "Null" ;
VAL_ 2148892493 M2D_IDX_CMD_Type_13 0 "Invalid" 2 "Code Index" 5 "Confirm Index" 6 "Exit Code" 7 "Start Code" 8 "Code Failed" 9 "Code Success" 10 "Invalid" 255 "Null" ;
VAL_ 2148892493 M2D_IDX_DCDC_Index_13 0 "Initial Index" 1 "Index 1" 2 "Index 2" 3 "Index 3" 4 "Index 4" 5 "Index 5" 6 "Index 6" 7 "Index 7" 8 "Index 8" 9 "Index 9" 10 "Index 10" 11 "Index 11" 12 "Index 12" 13 "Index 13" 14 "Index 14" 15 "Index 15" 255 "Null" ;
VAL_ 2148892494 M2D_IDX_CMD_Type_14 0 "Invalid" 2 "Code Index" 5 "Confirm Index" 6 "Exit Code" 7 "Start Code" 8 "Code Failed" 9 "Code Success" 10 "Invalid" 255 "Null" ;
VAL_ 2148892494 M2D_IDX_DCDC_Index_14 0 "Initial Index" 1 "Index 1" 2 "Index 2" 3 "Index 3" 4 "Index 4" 5 "Index 5" 6 "Index 6" 7 "Index 7" 8 "Index 8" 9 "Index 9" 10 "Index 10" 11 "Index 11" 12 "Index 12" 13 "Index 13" 14 "Index 14" 15 "Index 15" 255 "Null" ;
VAL_ 2148892495 M2D_IDX_CMD_Type_15 0 "Invalid" 2 "Code Index" 5 "Confirm Index" 6 "Exit Code" 7 "Start Code" 8 "Code Failed" 9 "Code Success" 10 "Invalid" 255 "Null" ;
VAL_ 2148892495 M2D_IDX_DCDC_Index_15 0 "Initial Index" 1 "Index 1" 2 "Index 2" 3 "Index 3" 4 "Index 4" 5 "Index 5" 6 "Index 6" 7 "Index 7" 8 "Index 8" 9 "Index 9" 10 "Index 10" 11 "Index 11" 12 "Index 12" 13 "Index 13" 14 "Index 14" 15 "Index 15" 255 "Null" ;
VAL_ 2148892496 M2D_IDX_CMD_Type_16 0 "Invalid" 2 "Code Index" 5 "Confirm Index" 6 "Exit Code" 7 "Start Code" 8 "Code Failed" 9 "Code Success" 10 "Invalid" 255 "Null" ;
VAL_ 2148892496 M2D_IDX_DCDC_Index_16 0 "Initial Index" 1 "Index 1" 2 "Index 2" 3 "Index 3" 4 "Index 4" 5 "Index 5" 6 "Index 6" 7 "Index 7" 8 "Index 8" 9 "Index 9" 10 "Index 10" 11 "Index 11" 12 "Index 12" 13 "Index 13" 14 "Index 14" 15 "Index 15" 255 "Null" ;
VAL_ 2148892497 M2D_IDX_CMD_Type_17 0 "Invalid" 2 "Code Index" 5 "Confirm Index" 6 "Exit Code" 7 "Start Code" 8 "Code Failed" 9 "Code Success" 10 "Invalid" 255 "Null" ;
VAL_ 2148892497 M2D_IDX_DCDC_Index_17 0 "Initial Index" 1 "Index 1" 2 "Index 2" 3 "Index 3" 4 "Index 4" 5 "Index 5" 6 "Index 6" 7 "Index 7" 8 "Index 8" 9 "Index 9" 10 "Index 10" 11 "Index 11" 12 "Index 12" 13 "Index 13" 14 "Index 14" 15 "Index 15" 255 "Null" ;
VAL_ 2148892498 M2D_IDX_CMD_Type_18 0 "Invalid" 2 "Code Index" 5 "Confirm Index" 6 "Exit Code" 7 "Start Code" 8 "Code Failed" 9 "Code Success" 10 "Invalid" 255 "Null" ;
VAL_ 2148892498 M2D_IDX_DCDC_Index_18 0 "Initial Index" 1 "Index 1" 2 "Index 2" 3 "Index 3" 4 "Index 4" 5 "Index 5" 6 "Index 6" 7 "Index 7" 8 "Index 8" 9 "Index 9" 10 "Index 10" 11 "Index 11" 12 "Index 12" 13 "Index 13" 14 "Index 14" 15 "Index 15" 255 "Null" ;
VAL_ 2148892499 M2D_IDX_CMD_Type_19 0 "Invalid" 2 "Code Index" 5 "Confirm Index" 6 "Exit Code" 7 "Start Code" 8 "Code Failed" 9 "Code Success" 10 "Invalid" 255 "Null" ;
VAL_ 2148892499 M2D_IDX_DCDC_Index_19 0 "Initial Index" 1 "Index 1" 2 "Index 2" 3 "Index 3" 4 "Index 4" 5 "Index 5" 6 "Index 6" 7 "Index 7" 8 "Index 8" 9 "Index 9" 10 "Index 10" 11 "Index 11" 12 "Index 12" 13 "Index 13" 14 "Index 14" 15 "Index 15" 255 "Null" ;
VAL_ 2148892500 M2D_IDX_CMD_Type_20 0 "Invalid" 2 "Code Index" 5 "Confirm Index" 6 "Exit Code" 7 "Start Code" 8 "Code Failed" 9 "Code Success" 10 "Invalid" 255 "Null" ;
VAL_ 2148892500 M2D_IDX_DCDC_Index_20 0 "Initial Index" 1 "Index 1" 2 "Index 2" 3 "Index 3" 4 "Index 4" 5 "Index 5" 6 "Index 6" 7 "Index 7" 8 "Index 8" 9 "Index 9" 10 "Index 10" 11 "Index 11" 12 "Index 12" 13 "Index 13" 14 "Index 14" 15 "Index 15" 255 "Null" ;
VAL_ 2148892501 M2D_IDX_CMD_Type_21 0 "Invalid" 2 "Code Index" 5 "Confirm Index" 6 "Exit Code" 7 "Start Code" 8 "Code Failed" 9 "Code Success" 10 "Invalid" 255 "Null" ;
VAL_ 2148892501 M2D_IDX_DCDC_Index_21 0 "Initial Index" 1 "Index 1" 2 "Index 2" 3 "Index 3" 4 "Index 4" 5 "Index 5" 6 "Index 6" 7 "Index 7" 8 "Index 8" 9 "Index 9" 10 "Index 10" 11 "Index 11" 12 "Index 12" 13 "Index 13" 14 "Index 14" 15 "Index 15" 255 "Null" ;
VAL_ 2148892502 M2D_IDX_CMD_Type_22 0 "Invalid" 2 "Code Index" 5 "Confirm Index" 6 "Exit Code" 7 "Start Code" 8 "Code Failed" 9 "Code Success" 10 "Invalid" 255 "Null" ;
VAL_ 2148892502 M2D_IDX_DCDC_Index_22 0 "Initial Index" 1 "Index 1" 2 "Index 2" 3 "Index 3" 4 "Index 4" 5 "Index 5" 6 "Index 6" 7 "Index 7" 8 "Index 8" 9 "Index 9" 10 "Index 10" 11 "Index 11" 12 "Index 12" 13 "Index 13" 14 "Index 14" 15 "Index 15" 255 "Null" ;
VAL_ 2148892503 M2D_IDX_CMD_Type_23 0 "Invalid" 2 "Code Index" 5 "Confirm Index" 6 "Exit Code" 7 "Start Code" 8 "Code Failed" 9 "Code Success" 10 "Invalid" 255 "Null" ;
VAL_ 2148892503 M2D_IDX_DCDC_Index_23 0 "Initial Index" 1 "Index 1" 2 "Index 2" 3 "Index 3" 4 "Index 4" 5 "Index 5" 6 "Index 6" 7 "Index 7" 8 "Index 8" 9 "Index 9" 10 "Index 10" 11 "Index 11" 12 "Index 12" 13 "Index 13" 14 "Index 14" 15 "Index 15" 255 "Null" ;
VAL_ 2148892504 M2D_IDX_CMD_Type_24 0 "Invalid" 2 "Code Index" 5 "Confirm Index" 6 "Exit Code" 7 "Start Code" 8 "Code Failed" 9 "Code Success" 10 "Invalid" 255 "Null" ;
VAL_ 2148892504 M2D_IDX_DCDC_Index_24 0 "Initial Index" 1 "Index 1" 2 "Index 2" 3 "Index 3" 4 "Index 4" 5 "Index 5" 6 "Index 6" 7 "Index 7" 8 "Index 8" 9 "Index 9" 10 "Index 10" 11 "Index 11" 12 "Index 12" 13 "Index 13" 14 "Index 14" 15 "Index 15" 255 "Null" ;
VAL_ 2148892505 M2D_IDX_CMD_Type_25 0 "Invalid" 2 "Code Index" 5 "Confirm Index" 6 "Exit Code" 7 "Start Code" 8 "Code Failed" 9 "Code Success" 10 "Invalid" 255 "Null" ;
VAL_ 2148892505 M2D_IDX_DCDC_Index_25 0 "Initial Index" 1 "Index 1" 2 "Index 2" 3 "Index 3" 4 "Index 4" 5 "Index 5" 6 "Index 6" 7 "Index 7" 8 "Index 8" 9 "Index 9" 10 "Index 10" 11 "Index 11" 12 "Index 12" 13 "Index 13" 14 "Index 14" 15 "Index 15" 255 "Null" ;
VAL_ 2148892506 M2D_IDX_CMD_Type_26 0 "Invalid" 2 "Code Index" 5 "Confirm Index" 6 "Exit Code" 7 "Start Code" 8 "Code Failed" 9 "Code Success" 10 "Invalid" 255 "Null" ;
VAL_ 2148892506 M2D_IDX_DCDC_Index_26 0 "Initial Index" 1 "Index 1" 2 "Index 2" 3 "Index 3" 4 "Index 4" 5 "Index 5" 6 "Index 6" 7 "Index 7" 8 "Index 8" 9 "Index 9" 10 "Index 10" 11 "Index 11" 12 "Index 12" 13 "Index 13" 14 "Index 14" 15 "Index 15" 255 "Null" ;
VAL_ 2148892507 M2D_IDX_CMD_Type_27 0 "Invalid" 2 "Code Index" 5 "Confirm Index" 6 "Exit Code" 7 "Start Code" 8 "Code Failed" 9 "Code Success" 10 "Invalid" 255 "Null" ;
VAL_ 2148892507 M2D_IDX_DCDC_Index_27 0 "Initial Index" 1 "Index 1" 2 "Index 2" 3 "Index 3" 4 "Index 4" 5 "Index 5" 6 "Index 6" 7 "Index 7" 8 "Index 8" 9 "Index 9" 10 "Index 10" 11 "Index 11" 12 "Index 12" 13 "Index 13" 14 "Index 14" 15 "Index 15" 255 "Null" ;
VAL_ 2148892508 M2D_IDX_CMD_Type_28 0 "Invalid" 2 "Code Index" 5 "Confirm Index" 6 "Exit Code" 7 "Start Code" 8 "Code Failed" 9 "Code Success" 10 "Invalid" 255 "Null" ;
VAL_ 2148892508 M2D_IDX_DCDC_Index_28 0 "Initial Index" 1 "Index 1" 2 "Index 2" 3 "Index 3" 4 "Index 4" 5 "Index 5" 6 "Index 6" 7 "Index 7" 8 "Index 8" 9 "Index 9" 10 "Index 10" 11 "Index 11" 12 "Index 12" 13 "Index 13" 14 "Index 14" 15 "Index 15" 255 "Null" ;
VAL_ 2148892509 M2D_IDX_CMD_Type_29 0 "Invalid" 2 "Code Index" 5 "Confirm Index" 6 "Exit Code" 7 "Start Code" 8 "Code Failed" 9 "Code Success" 10 "Invalid" 255 "Null" ;
VAL_ 2148892509 M2D_IDX_DCDC_Index_29 0 "Initial Index" 1 "Index 1" 2 "Index 2" 3 "Index 3" 4 "Index 4" 5 "Index 5" 6 "Index 6" 7 "Index 7" 8 "Index 8" 9 "Index 9" 10 "Index 10" 11 "Index 11" 12 "Index 12" 13 "Index 13" 14 "Index 14" 15 "Index 15" 255 "Null" ;
VAL_ 2148892510 M2D_IDX_CMD_Type_30 0 "Invalid" 2 "Code Index" 5 "Confirm Index" 6 "Exit Code" 7 "Start Code" 8 "Code Failed" 9 "Code Success" 10 "Invalid" 255 "Null" ;
VAL_ 2148892510 M2D_IDX_DCDC_Index_30 0 "Initial Index" 1 "Index 1" 2 "Index 2" 3 "Index 3" 4 "Index 4" 5 "Index 5" 6 "Index 6" 7 "Index 7" 8 "Index 8" 9 "Index 9" 10 "Index 10" 11 "Index 11" 12 "Index 12" 13 "Index 13" 14 "Index 14" 15 "Index 15" 255 "Null" ;
VAL_ 2148892511 M2D_IDX_CMD_Type_31 0 "Invalid" 2 "Code Index" 5 "Confirm Index" 6 "Exit Code" 7 "Start Code" 8 "Code Failed" 9 "Code Success" 10 "Invalid" 255 "Null" ;
VAL_ 2148892511 M2D_IDX_DCDC_Index_31 0 "Initial Index" 1 "Index 1" 2 "Index 2" 3 "Index 3" 4 "Index 4" 5 "Index 5" 6 "Index 6" 7 "Index 7" 8 "Index 8" 9 "Index 9" 10 "Index 10" 11 "Index 11" 12 "Index 12" 13 "Index 13" 14 "Index 14" 15 "Index 15" 255 "Null" ;
VAL_ 2148892512 M2D_IDX_CMD_Type_32 0 "Invalid" 2 "Code Index" 5 "Confirm Index" 6 "Exit Code" 7 "Start Code" 8 "Code Failed" 9 "Code Success" 10 "Invalid" 255 "Null" ;
VAL_ 2148892512 M2D_IDX_DCDC_Index_32 0 "Initial Index" 1 "Index 1" 2 "Index 2" 3 "Index 3" 4 "Index 4" 5 "Index 5" 6 "Index 6" 7 "Index 7" 8 "Index 8" 9 "Index 9" 10 "Index 10" 11 "Index 11" 12 "Index 12" 13 "Index 13" 14 "Index 14" 15 "Index 15" 255 "Null" ;
VAL_ 2148892513 M2D_IDX_CMD_Type_33 0 "Invalid" 2 "Code Index" 5 "Confirm Index" 6 "Exit Code" 7 "Start Code" 8 "Code Failed" 9 "Code Success" 10 "Invalid" 255 "Null" ;
VAL_ 2148892513 M2D_IDX_DCDC_Index_33 0 "Initial Index" 1 "Index 1" 2 "Index 2" 3 "Index 3" 4 "Index 4" 5 "Index 5" 6 "Index 6" 7 "Index 7" 8 "Index 8" 9 "Index 9" 10 "Index 10" 11 "Index 11" 12 "Index 12" 13 "Index 13" 14 "Index 14" 15 "Index 15" 255 "Null" ;
VAL_ 2148892514 M2D_IDX_CMD_Type_34 0 "Invalid" 2 "Code Index" 5 "Confirm Index" 6 "Exit Code" 7 "Start Code" 8 "Code Failed" 9 "Code Success" 10 "Invalid" 255 "Null" ;
VAL_ 2148892514 M2D_IDX_DCDC_Index_34 0 "Initial Index" 1 "Index 1" 2 "Index 2" 3 "Index 3" 4 "Index 4" 5 "Index 5" 6 "Index 6" 7 "Index 7" 8 "Index 8" 9 "Index 9" 10 "Index 10" 11 "Index 11" 12 "Index 12" 13 "Index 13" 14 "Index 14" 15 "Index 15" 255 "Null" ;
VAL_ 2148892515 M2D_IDX_CMD_Type_35 0 "Invalid" 2 "Code Index" 5 "Confirm Index" 6 "Exit Code" 7 "Start Code" 8 "Code Failed" 9 "Code Success" 10 "Invalid" 255 "Null" ;
VAL_ 2148892515 M2D_IDX_DCDC_Index_35 0 "Initial Index" 1 "Index 1" 2 "Index 2" 3 "Index 3" 4 "Index 4" 5 "Index 5" 6 "Index 6" 7 "Index 7" 8 "Index 8" 9 "Index 9" 10 "Index 10" 11 "Index 11" 12 "Index 12" 13 "Index 13" 14 "Index 14" 15 "Index 15" 255 "Null" ;
VAL_ 2148892516 M2D_IDX_CMD_Type_36 0 "Invalid" 2 "Code Index" 5 "Confirm Index" 6 "Exit Code" 7 "Start Code" 8 "Code Failed" 9 "Code Success" 10 "Invalid" 255 "Null" ;
VAL_ 2148892516 M2D_IDX_DCDC_Index_36 0 "Initial Index" 1 "Index 1" 2 "Index 2" 3 "Index 3" 4 "Index 4" 5 "Index 5" 6 "Index 6" 7 "Index 7" 8 "Index 8" 9 "Index 9" 10 "Index 10" 11 "Index 11" 12 "Index 12" 13 "Index 13" 14 "Index 14" 15 "Index 15" 255 "Null" ;
VAL_ 2148892517 M2D_IDX_CMD_Type_37 0 "Invalid" 2 "Code Index" 5 "Confirm Index" 6 "Exit Code" 7 "Start Code" 8 "Code Failed" 9 "Code Success" 10 "Invalid" 255 "Null" ;
VAL_ 2148892517 M2D_IDX_DCDC_Index_37 0 "Initial Index" 1 "Index 1" 2 "Index 2" 3 "Index 3" 4 "Index 4" 5 "Index 5" 6 "Index 6" 7 "Index 7" 8 "Index 8" 9 "Index 9" 10 "Index 10" 11 "Index 11" 12 "Index 12" 13 "Index 13" 14 "Index 14" 15 "Index 15" 255 "Null" ;
VAL_ 2148892518 M2D_IDX_CMD_Type_38 0 "Invalid" 2 "Code Index" 5 "Confirm Index" 6 "Exit Code" 7 "Start Code" 8 "Code Failed" 9 "Code Success" 10 "Invalid" 255 "Null" ;
VAL_ 2148892518 M2D_IDX_DCDC_Index_38 0 "Initial Index" 1 "Index 1" 2 "Index 2" 3 "Index 3" 4 "Index 4" 5 "Index 5" 6 "Index 6" 7 "Index 7" 8 "Index 8" 9 "Index 9" 10 "Index 10" 11 "Index 11" 12 "Index 12" 13 "Index 13" 14 "Index 14" 15 "Index 15" 255 "Null" ;
VAL_ 2148892519 M2D_IDX_CMD_Type_39 0 "Invalid" 2 "Code Index" 5 "Confirm Index" 6 "Exit Code" 7 "Start Code" 8 "Code Failed" 9 "Code Success" 10 "Invalid" 255 "Null" ;
VAL_ 2148892519 M2D_IDX_DCDC_Index_39 0 "Initial Index" 1 "Index 1" 2 "Index 2" 3 "Index 3" 4 "Index 4" 5 "Index 5" 6 "Index 6" 7 "Index 7" 8 "Index 8" 9 "Index 9" 10 "Index 10" 11 "Index 11" 12 "Index 12" 13 "Index 13" 14 "Index 14" 15 "Index 15" 255 "Null" ;
VAL_ 2148892520 M2D_IDX_CMD_Type_40 0 "Invalid" 2 "Code Index" 5 "Confirm Index" 6 "Exit Code" 7 "Start Code" 8 "Code Failed" 9 "Code Success" 10 "Invalid" 255 "Null" ;
VAL_ 2148892520 M2D_IDX_DCDC_Index_40 0 "Initial Index" 1 "Index 1" 2 "Index 2" 3 "Index 3" 4 "Index 4" 5 "Index 5" 6 "Index 6" 7 "Index 7" 8 "Index 8" 9 "Index 9" 10 "Index 10" 11 "Index 11" 12 "Index 12" 13 "Index 13" 14 "Index 14" 15 "Index 15" 255 "Null" ;
VERSION ""

NS_ :

BS_:

BU_: MBMU PC SBMU IMM ETH DCDC LEMS

BO_ 2148892521 M2D_CMD2__41: 8 MBMU
 SG_ M2D_CMD2_CRC_41 : 0|8@1+ (1,0) [0|255] ""  DCDC
 SG_ M2D_IDX_CMD_Type_41 : 8|8@1+ (1,0) [0|255] ""  DCDC
 SG_ M2D_IDX_DCDC_Index_41 : 16|8@1+ (1,0) [0|255] ""  DCDC
 SG_ M2D_IDX_DCDC_Matchingcode_41 : 24|8@1+ (1,0) [0|255] ""  DCDC
 SG_ M2D_IDX_Reserved_41 : 32|32@1+ (1,0) [0|4294967295] ""  DCDC

BO_ 2148892522 M2D_CMD2__42: 8 MBMU
 SG_ M2D_CMD2_CRC_42 : 0|8@1+ (1,0) [0|255] ""  DCDC
 SG_ M2D_IDX_CMD_Type_42 : 8|8@1+ (1,0) [0|255] ""  DCDC
 SG_ M2D_IDX_DCDC_Index_42 : 16|8@1+ (1,0) [0|255] ""  DCDC
 SG_ M2D_IDX_DCDC_Matchingcode_42 : 24|8@1+ (1,0) [0|255] ""  DCDC
 SG_ M2D_IDX_Reserved_42 : 32|32@1+ (1,0) [0|4294967295] ""  DCDC

BO_ 2148892523 M2D_CMD2__43: 8 MBMU
 SG_ M2D_CMD2_CRC_43 : 0|8@1+ (1,0) [0|255] ""  DCDC
 SG_ M2D_IDX_CMD_Type_43 : 8|8@1+ (1,0) [0|255] ""  DCDC
 SG_ M2D_IDX_DCDC_Index_43 : 16|8@1+ (1,0) [0|255] ""  DCDC
 SG_ M2D_IDX_DCDC_Matchingcode_43 : 24|8@1+ (1,0) [0|255] ""  DCDC
 SG_ M2D_IDX_Reserved_43 : 32|32@1+ (1,0) [0|4294967295] ""  DCDC

BO_ 2148892524 M2D_CMD2__44: 8 MBMU
 SG_ M2D_CMD2_CRC_44 : 0|8@1+ (1,0) [0|255] ""  DCDC
 SG_ M2D_IDX_CMD_Type_44 : 8|8@1+ (1,0) [0|255] ""  DCDC
 SG_ M2D_IDX_DCDC_Index_44 : 16|8@1+ (1,0) [0|255] ""  DCDC
 SG_ M2D_IDX_DCDC_Matchingcode_44 : 24|8@1+ (1,0) [0|255] ""  DCDC
 SG_ M2D_IDX_Reserved_44 : 32|32@1+ (1,0) [0|4294967295] ""  DCDC

BO_ 2148892525 M2D_CMD2__45: 8 MBMU
 SG_ M2D_CMD2_CRC_45 : 0|8@1+ (1,0) [0|255] ""  DCDC
 SG_ M2D_IDX_CMD_Type_45 : 8|8@1+ (1,0) [0|255] ""  DCDC
 SG_ M2D_IDX_DCDC_Index_45 : 16|8@1+ (1,0) [0|255] ""  DCDC
 SG_ M2D_IDX_DCDC_Matchingcode_45 : 24|8@1+ (1,0) [0|255] ""  DCDC
 SG_ M2D_IDX_Reserved_45 : 32|32@1+ (1,0) [0|4294967295] ""  DCDC

BO_ 2148892526 M2D_CMD2__46: 8 MBMU
 SG_ M2D_CMD2_CRC_46 : 0|8@1+ (1,0) [0|255] ""  DCDC
 SG_ M2D_IDX_CMD_Type_46 : 8|8@1+ (1,0) [0|255] ""  DCDC
 SG_ M2D_IDX_DCDC_Index_46 : 16|8@1+ (1,0) [0|255] ""  DCDC
 SG_ M2D_IDX_DCDC_Matchingcode_46 : 24|8@1+ (1,0) [0|255] ""  DCDC
 SG_ M2D_IDX_Reserved_46 : 32|32@1+ (1,0) [0|4294967295] ""  DCDC

BO_ 2148892527 M2D_CMD2__47: 8 MBMU
 SG_ M2D_CMD2_CRC_47 : 0|8@1+ (1,0) [0|255] ""  DCDC
 SG_ M2D_IDX_CMD_Type_47 : 8|8@1+ (1,0) [0|255] ""  DCDC
 SG_ M2D_IDX_DCDC_Index_47 : 16|8@1+ (1,0) [0|255] ""  DCDC
 SG_ M2D_IDX_DCDC_Matchingcode_47 : 24|8@1+ (1,0) [0|255] ""  DCDC
 SG_ M2D_IDX_Reserved_47 : 32|32@1+ (1,0) [0|4294967295] ""  DCDC

BO_ 2148892528 M2D_CMD2__48: 8 MBMU
 SG_ M2D_CMD2_CRC_48 : 0|8@1+ (1,0) [0|255] ""  DCDC
 SG_ M2D_IDX_CMD_Type_48 : 8|8@1+ (1,0) [0|255] ""  DCDC
 SG_ M2D_IDX_DCDC_Index_48 : 16|8@1+ (1,0) [0|255] ""  DCDC
 SG_ M2D_IDX_DCDC_Matchingcode_48 : 24|8@1+ (1,0) [0|255] ""  DCDC
 SG_ M2D_IDX_Reserved_48 : 32|32@1+ (1,0) [0|4294967295] ""  DCDC

BO_ 2148892529 M2D_CMD2__49: 8 MBMU
 SG_ M2D_CMD2_CRC_49 : 0|8@1+ (1,0) [0|255] ""  DCDC
 SG_ M2D_IDX_CMD_Type_49 : 8|8@1+ (1,0) [0|255] ""  DCDC
 SG_ M2D_IDX_DCDC_Index_49 : 16|8@1+ (1,0) [0|255] ""  DCDC
 SG_ M2D_IDX_DCDC_Matchingcode_49 : 24|8@1+ (1,0) [0|255] ""  DCDC
 SG_ M2D_IDX_Reserved_49 : 32|32@1+ (1,0) [0|4294967295] ""  DCDC

BO_ 2148892530 M2D_CMD2__50: 8 MBMU
 SG_ M2D_CMD2_CRC_50 : 0|8@1+ (1,0) [0|255] ""  DCDC
 SG_ M2D_IDX_CMD_Type_50 : 8|8@1+ (1,0) [0|255] ""  DCDC
 SG_ M2D_IDX_DCDC_Index_50 : 16|8@1+ (1,0) [0|255] ""  DCDC
 SG_ M2D_IDX_DCDC_Matchingcode_50 : 24|8@1+ (1,0) [0|255] ""  DCDC
 SG_ M2D_IDX_Reserved_50 : 32|32@1+ (1,0) [0|4294967295] ""  DCDC

BO_ 2148892531 M2D_CMD2__51: 8 MBMU
 SG_ M2D_CMD2_CRC_51 : 0|8@1+ (1,0) [0|255] ""  DCDC
 SG_ M2D_IDX_CMD_Type_51 : 8|8@1+ (1,0) [0|255] ""  DCDC
 SG_ M2D_IDX_DCDC_Index_51 : 16|8@1+ (1,0) [0|255] ""  DCDC
 SG_ M2D_IDX_DCDC_Matchingcode_51 : 24|8@1+ (1,0) [0|255] ""  DCDC
 SG_ M2D_IDX_Reserved_51 : 32|32@1+ (1,0) [0|4294967295] ""  DCDC

BO_ 2148892532 M2D_CMD2__52: 8 MBMU
 SG_ M2D_CMD2_CRC_52 : 0|8@1+ (1,0) [0|255] ""  DCDC
 SG_ M2D_IDX_CMD_Type_52 : 8|8@1+ (1,0) [0|255] ""  DCDC
 SG_ M2D_IDX_DCDC_Index_52 : 16|8@1+ (1,0) [0|255] ""  DCDC
 SG_ M2D_IDX_DCDC_Matchingcode_52 : 24|8@1+ (1,0) [0|255] ""  DCDC
 SG_ M2D_IDX_Reserved_52 : 32|32@1+ (1,0) [0|4294967295] ""  DCDC

BO_ 2148892533 M2D_CMD2__53: 8 MBMU
 SG_ M2D_CMD2_CRC_53 : 0|8@1+ (1,0) [0|255] ""  DCDC
 SG_ M2D_IDX_CMD_Type_53 : 8|8@1+ (1,0) [0|255] ""  DCDC
 SG_ M2D_IDX_DCDC_Index_53 : 16|8@1+ (1,0) [0|255] ""  DCDC
 SG_ M2D_IDX_DCDC_Matchingcode_53 : 24|8@1+ (1,0) [0|255] ""  DCDC
 SG_ M2D_IDX_Reserved_53 : 32|32@1+ (1,0) [0|4294967295] ""  DCDC

BO_ 2148892534 M2D_CMD2__54: 8 MBMU
 SG_ M2D_CMD2_CRC_54 : 0|8@1+ (1,0) [0|255] ""  DCDC
 SG_ M2D_IDX_CMD_Type_54 : 8|8@1+ (1,0) [0|255] ""  DCDC
 SG_ M2D_IDX_DCDC_Index_54 : 16|8@1+ (1,0) [0|255] ""  DCDC
 SG_ M2D_IDX_DCDC_Matchingcode_54 : 24|8@1+ (1,0) [0|255] ""  DCDC
 SG_ M2D_IDX_Reserved_54 : 32|32@1+ (1,0) [0|4294967295] ""  DCDC

BO_ 2148892535 M2D_CMD2__55: 8 MBMU
 SG_ M2D_CMD2_CRC_55 : 0|8@1+ (1,0) [0|255] ""  DCDC
 SG_ M2D_IDX_CMD_Type_55 : 8|8@1+ (1,0) [0|255] ""  DCDC
 SG_ M2D_IDX_DCDC_Index_55 : 16|8@1+ (1,0) [0|255] ""  DCDC
 SG_ M2D_IDX_DCDC_Matchingcode_55 : 24|8@1+ (1,0) [0|255] ""  DCDC
 SG_ M2D_IDX_Reserved_55 : 32|32@1+ (1,0) [0|4294967295] ""  DCDC

BO_ 2148892536 M2D_CMD2__56: 8 MBMU
 SG_ M2D_CMD2_CRC_56 : 0|8@1+ (1,0) [0|255] ""  DCDC
 SG_ M2D_IDX_CMD_Type_56 : 8|8@1+ (1,0) [0|255] ""  DCDC
 SG_ M2D_IDX_DCDC_Index_56 : 16|8@1+ (1,0) [0|255] ""  DCDC
 SG_ M2D_IDX_DCDC_Matchingcode_56 : 24|8@1+ (1,0) [0|255] ""  DCDC
 SG_ M2D_IDX_Reserved_56 : 32|32@1+ (1,0) [0|4294967295] ""  DCDC

BO_ 2148892537 M2D_CMD2__57: 8 MBMU
 SG_ M2D_CMD2_CRC_57 : 0|8@1+ (1,0) [0|255] ""  DCDC
 SG_ M2D_IDX_CMD_Type_57 : 8|8@1+ (1,0) [0|255] ""  DCDC
 SG_ M2D_IDX_DCDC_Index_57 : 16|8@1+ (1,0) [0|255] ""  DCDC
 SG_ M2D_IDX_DCDC_Matchingcode_57 : 24|8@1+ (1,0) [0|255] ""  DCDC
 SG_ M2D_IDX_Reserved_57 : 32|32@1+ (1,0) [0|4294967295] ""  DCDC

BO_ 2148892538 M2D_CMD2__58: 8 MBMU
 SG_ M2D_CMD2_CRC_58 : 0|8@1+ (1,0) [0|255] ""  DCDC
 SG_ M2D_IDX_CMD_Type_58 : 8|8@1+ (1,0) [0|255] ""  DCDC
 SG_ M2D_IDX_DCDC_Index_58 : 16|8@1+ (1,0) [0|255] ""  DCDC
 SG_ M2D_IDX_DCDC_Matchingcode_58 : 24|8@1+ (1,0) [0|255] ""  DCDC
 SG_ M2D_IDX_Reserved_58 : 32|32@1+ (1,0) [0|4294967295] ""  DCDC

BO_ 2148892539 M2D_CMD2__59: 8 MBMU
 SG_ M2D_CMD2_CRC_59 : 0|8@1+ (1,0) [0|255] ""  DCDC
 SG_ M2D_IDX_CMD_Type_59 : 8|8@1+ (1,0) [0|255] ""  DCDC
 SG_ M2D_IDX_DCDC_Index_59 : 16|8@1+ (1,0) [0|255] ""  DCDC
 SG_ M2D_IDX_DCDC_Matchingcode_59 : 24|8@1+ (1,0) [0|255] ""  DCDC
 SG_ M2D_IDX_Reserved_59 : 32|32@1+ (1,0) [0|4294967295] ""  DCDC

BO_ 2148892540 M2D_CMD2__60: 8 MBMU
 SG_ M2D_CMD2_CRC_60 : 0|8@1+ (1,0) [0|255] ""  DCDC
 SG_ M2D_IDX_CMD_Type_60 : 8|8@1+ (1,0) [0|255] ""  DCDC
 SG_ M2D_IDX_DCDC_Index_60 : 16|8@1+ (1,0) [0|255] ""  DCDC
 SG_ M2D_IDX_DCDC_Matchingcode_60 : 24|8@1+ (1,0) [0|255] ""  DCDC
 SG_ M2D_IDX_Reserved_60 : 32|32@1+ (1,0) [0|4294967295] ""  DCDC

BO_ 2148892541 M2D_CMD2__61: 8 MBMU
 SG_ M2D_CMD2_CRC_61 : 0|8@1+ (1,0) [0|255] ""  DCDC
 SG_ M2D_IDX_CMD_Type_61 : 8|8@1+ (1,0) [0|255] ""  DCDC
 SG_ M2D_IDX_DCDC_Index_61 : 16|8@1+ (1,0) [0|255] ""  DCDC
 SG_ M2D_IDX_DCDC_Matchingcode_61 : 24|8@1+ (1,0) [0|255] ""  DCDC
 SG_ M2D_IDX_Reserved_61 : 32|32@1+ (1,0) [0|4294967295] ""  DCDC

BO_ 2148892542 M2D_CMD2__62: 8 MBMU
 SG_ M2D_CMD2_CRC_62 : 0|8@1+ (1,0) [0|255] ""  DCDC
 SG_ M2D_IDX_CMD_Type_62 : 8|8@1+ (1,0) [0|255] ""  DCDC
 SG_ M2D_IDX_DCDC_Index_62 : 16|8@1+ (1,0) [0|255] ""  DCDC
 SG_ M2D_IDX_DCDC_Matchingcode_62 : 24|8@1+ (1,0) [0|255] ""  DCDC
 SG_ M2D_IDX_Reserved_62 : 32|32@1+ (1,0) [0|4294967295] ""  DCDC

BO_ 2148892543 M2D_CMD2__63: 8 MBMU
 SG_ M2D_CMD2_CRC_63 : 0|8@1+ (1,0) [0|255] ""  DCDC
 SG_ M2D_IDX_CMD_Type_63 : 8|8@1+ (1,0) [0|255] ""  DCDC
 SG_ M2D_IDX_DCDC_Index_63 : 16|8@1+ (1,0) [0|255] ""  DCDC
 SG_ M2D_IDX_DCDC_Matchingcode_63 : 24|8@1+ (1,0) [0|255] ""  DCDC
 SG_ M2D_IDX_Reserved_63 : 32|32@1+ (1,0) [0|4294967295] ""  DCDC

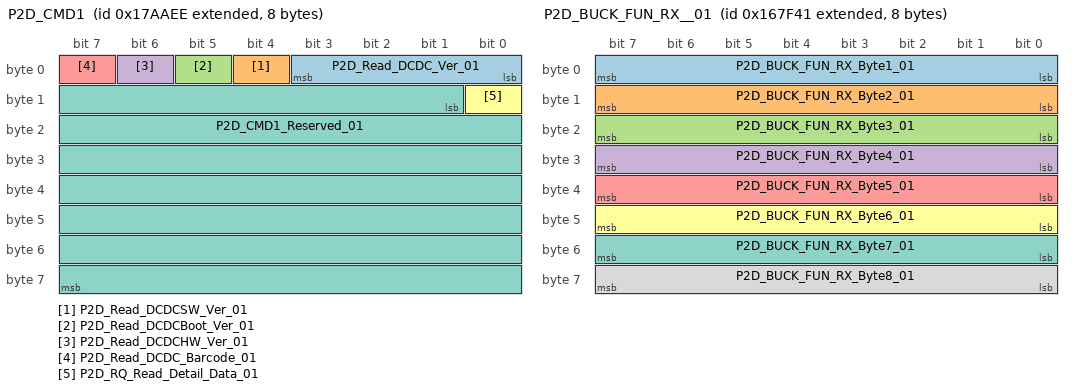
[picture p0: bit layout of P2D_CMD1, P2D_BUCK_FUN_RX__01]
BO_ 2149034734 P2D_CMD1: 8 PC
 SG_ P2D_Read_DCDC_Ver_01 : 0|4@1+ (1,0) [0|15] ""  DCDC
 SG_ P2D_Read_DCDCSW_Ver_01 : 4|1@1+ (1,0) [0|1] ""  DCDC
 SG_ P2D_Read_DCDCBoot_Ver_01 : 5|1@1+ (1,0) [0|1] ""  DCDC
 SG_ P2D_Read_DCDCHW_Ver_01 : 6|1@1+ (1,0) [0|1] ""  DCDC
 SG_ P2D_Read_DCDC_Barcode_01 : 7|1@1+ (1,0) [0|1] ""  DCDC
 SG_ P2D_RQ_Read_Detail_Data_01 : 8|1@1+ (1,0) [0|1] ""  DCDC
 SG_ P2D_CMD1_Reserved_01 : 9|55@1+ (1,0) [0|3.6028797018964E+016] ""  DCDC

BO_ 2148958017 P2D_BUCK_FUN_RX__01: 8 PC
 SG_ P2D_BUCK_FUN_RX_Byte1_01 : 0|8@1+ (1,0) [0|255] ""  DCDC
 SG_ P2D_BUCK_FUN_RX_Byte2_01 : 8|8@1+ (1,0) [0|255] ""  DCDC
 SG_ P2D_BUCK_FUN_RX_Byte3_01 : 16|8@1+ (1,0) [0|255] ""  DCDC
 SG_ P2D_BUCK_FUN_RX_Byte4_01 : 24|8@1+ (1,0) [0|255] ""  DCDC
 SG_ P2D_BUCK_FUN_RX_Byte5_01 : 32|8@1+ (1,0) [0|255] ""  DCDC
 SG_ P2D_BUCK_FUN_RX_Byte6_01 : 40|8@1+ (1,0) [0|255] ""  DCDC
 SG_ P2D_BUCK_FUN_RX_Byte7_01 : 48|8@1+ (1,0) [0|255] ""  DCDC
 SG_ P2D_BUCK_FUN_RX_Byte8_01 : 56|8@1+ (1,0) [0|255] ""  DCDC

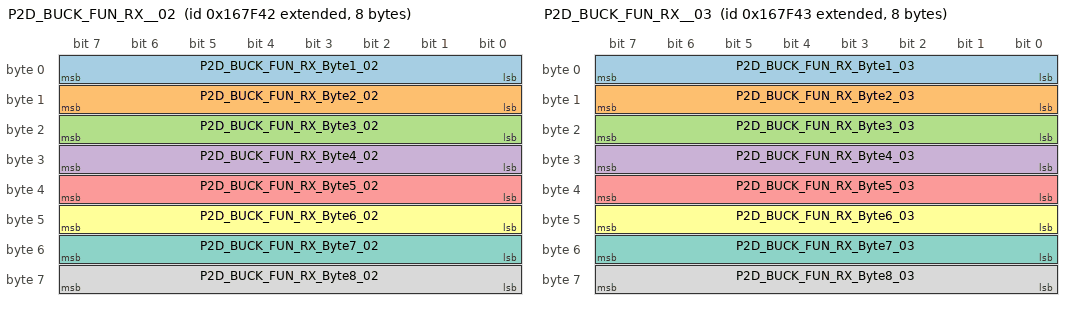
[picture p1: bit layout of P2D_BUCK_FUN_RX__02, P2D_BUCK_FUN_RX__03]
BO_ 2148958018 P2D_BUCK_FUN_RX__02: 8 PC
 SG_ P2D_BUCK_FUN_RX_Byte1_02 : 0|8@1+ (1,0) [0|255] ""  DCDC
 SG_ P2D_BUCK_FUN_RX_Byte2_02 : 8|8@1+ (1,0) [0|255] ""  DCDC
 SG_ P2D_BUCK_FUN_RX_Byte3_02 : 16|8@1+ (1,0) [0|255] ""  DCDC
 SG_ P2D_BUCK_FUN_RX_Byte4_02 : 24|8@1+ (1,0) [0|255] ""  DCDC
 SG_ P2D_BUCK_FUN_RX_Byte5_02 : 32|8@1+ (1,0) [0|255] ""  DCDC
 SG_ P2D_BUCK_FUN_RX_Byte6_02 : 40|8@1+ (1,0) [0|255] ""  DCDC
 SG_ P2D_BUCK_FUN_RX_Byte7_02 : 48|8@1+ (1,0) [0|255] ""  DCDC
 SG_ P2D_BUCK_FUN_RX_Byte8_02 : 56|8@1+ (1,0) [0|255] ""  DCDC

BO_ 2148958019 P2D_BUCK_FUN_RX__03: 8 PC
 SG_ P2D_BUCK_FUN_RX_Byte1_03 : 0|8@1+ (1,0) [0|255] ""  DCDC
 SG_ P2D_BUCK_FUN_RX_Byte2_03 : 8|8@1+ (1,0) [0|255] ""  DCDC
 SG_ P2D_BUCK_FUN_RX_Byte3_03 : 16|8@1+ (1,0) [0|255] ""  DCDC
 SG_ P2D_BUCK_FUN_RX_Byte4_03 : 24|8@1+ (1,0) [0|255] ""  DCDC
 SG_ P2D_BUCK_FUN_RX_Byte5_03 : 32|8@1+ (1,0) [0|255] ""  DCDC
 SG_ P2D_BUCK_FUN_RX_Byte6_03 : 40|8@1+ (1,0) [0|255] ""  DCDC
 SG_ P2D_BUCK_FUN_RX_Byte7_03 : 48|8@1+ (1,0) [0|255] ""  DCDC
 SG_ P2D_BUCK_FUN_RX_Byte8_03 : 56|8@1+ (1,0) [0|255] ""  DCDC

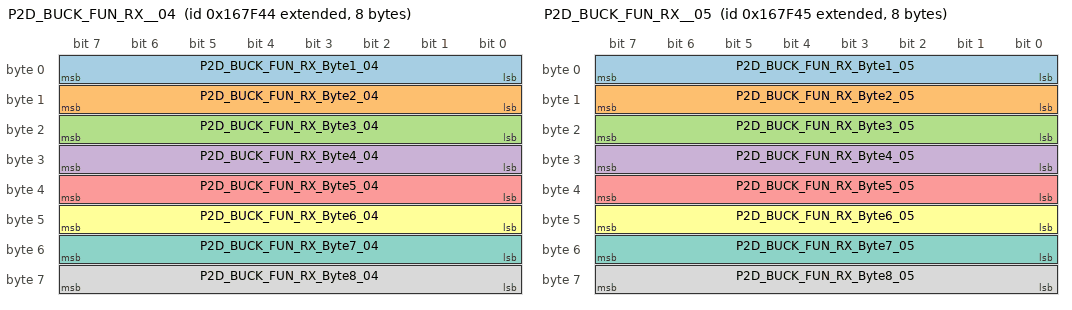
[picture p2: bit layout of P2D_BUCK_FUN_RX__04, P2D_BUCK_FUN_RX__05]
BO_ 2148958020 P2D_BUCK_FUN_RX__04: 8 PC
 SG_ P2D_BUCK_FUN_RX_Byte1_04 : 0|8@1+ (1,0) [0|255] ""  DCDC
 SG_ P2D_BUCK_FUN_RX_Byte2_04 : 8|8@1+ (1,0) [0|255] ""  DCDC
 SG_ P2D_BUCK_FUN_RX_Byte3_04 : 16|8@1+ (1,0) [0|255] ""  DCDC
 SG_ P2D_BUCK_FUN_RX_Byte4_04 : 24|8@1+ (1,0) [0|255] ""  DCDC
 SG_ P2D_BUCK_FUN_RX_Byte5_04 : 32|8@1+ (1,0) [0|255] ""  DCDC
 SG_ P2D_BUCK_FUN_RX_Byte6_04 : 40|8@1+ (1,0) [0|255] ""  DCDC
 SG_ P2D_BUCK_FUN_RX_Byte7_04 : 48|8@1+ (1,0) [0|255] ""  DCDC
 SG_ P2D_BUCK_FUN_RX_Byte8_04 : 56|8@1+ (1,0) [0|255] ""  DCDC

BO_ 2148958021 P2D_BUCK_FUN_RX__05: 8 PC
 SG_ P2D_BUCK_FUN_RX_Byte1_05 : 0|8@1+ (1,0) [0|255] ""  DCDC
 SG_ P2D_BUCK_FUN_RX_Byte2_05 : 8|8@1+ (1,0) [0|255] ""  DCDC
 SG_ P2D_BUCK_FUN_RX_Byte3_05 : 16|8@1+ (1,0) [0|255] ""  DCDC
 SG_ P2D_BUCK_FUN_RX_Byte4_05 : 24|8@1+ (1,0) [0|255] ""  DCDC
 SG_ P2D_BUCK_FUN_RX_Byte5_05 : 32|8@1+ (1,0) [0|255] ""  DCDC
 SG_ P2D_BUCK_FUN_RX_Byte6_05 : 40|8@1+ (1,0) [0|255] ""  DCDC
 SG_ P2D_BUCK_FUN_RX_Byte7_05 : 48|8@1+ (1,0) [0|255] ""  DCDC
 SG_ P2D_BUCK_FUN_RX_Byte8_05 : 56|8@1+ (1,0) [0|255] ""  DCDC

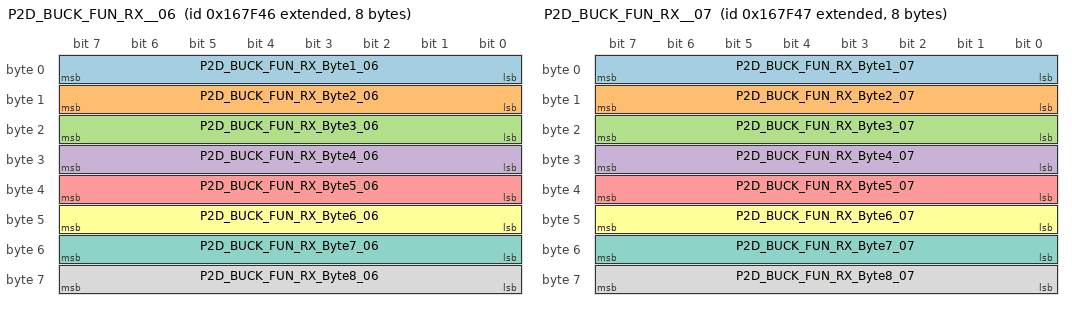
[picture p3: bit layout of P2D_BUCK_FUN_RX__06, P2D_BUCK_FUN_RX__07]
BO_ 2148958022 P2D_BUCK_FUN_RX__06: 8 PC
 SG_ P2D_BUCK_FUN_RX_Byte1_06 : 0|8@1+ (1,0) [0|255] ""  DCDC
 SG_ P2D_BUCK_FUN_RX_Byte2_06 : 8|8@1+ (1,0) [0|255] ""  DCDC
 SG_ P2D_BUCK_FUN_RX_Byte3_06 : 16|8@1+ (1,0) [0|255] ""  DCDC
 SG_ P2D_BUCK_FUN_RX_Byte4_06 : 24|8@1+ (1,0) [0|255] ""  DCDC
 SG_ P2D_BUCK_FUN_RX_Byte5_06 : 32|8@1+ (1,0) [0|255] ""  DCDC
 SG_ P2D_BUCK_FUN_RX_Byte6_06 : 40|8@1+ (1,0) [0|255] ""  DCDC
 SG_ P2D_BUCK_FUN_RX_Byte7_06 : 48|8@1+ (1,0) [0|255] ""  DCDC
 SG_ P2D_BUCK_FUN_RX_Byte8_06 : 56|8@1+ (1,0) [0|255] ""  DCDC

BO_ 2148958023 P2D_BUCK_FUN_RX__07: 8 PC
 SG_ P2D_BUCK_FUN_RX_Byte1_07 : 0|8@1+ (1,0) [0|255] ""  DCDC
 SG_ P2D_BUCK_FUN_RX_Byte2_07 : 8|8@1+ (1,0) [0|255] ""  DCDC
 SG_ P2D_BUCK_FUN_RX_Byte3_07 : 16|8@1+ (1,0) [0|255] ""  DCDC
 SG_ P2D_BUCK_FUN_RX_Byte4_07 : 24|8@1+ (1,0) [0|255] ""  DCDC
 SG_ P2D_BUCK_FUN_RX_Byte5_07 : 32|8@1+ (1,0) [0|255] ""  DCDC
 SG_ P2D_BUCK_FUN_RX_Byte6_07 : 40|8@1+ (1,0) [0|255] ""  DCDC
 SG_ P2D_BUCK_FUN_RX_Byte7_07 : 48|8@1+ (1,0) [0|255] ""  DCDC
 SG_ P2D_BUCK_FUN_RX_Byte8_07 : 56|8@1+ (1,0) [0|255] ""  DCDC

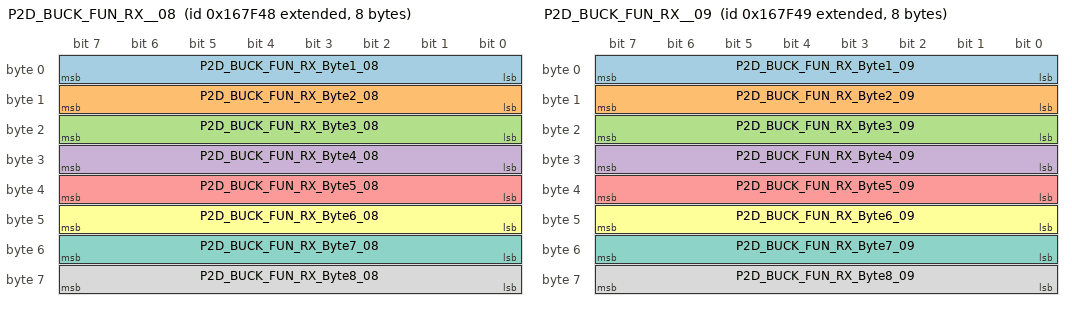
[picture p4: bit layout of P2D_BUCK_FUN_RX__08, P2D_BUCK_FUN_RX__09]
BO_ 2148958024 P2D_BUCK_FUN_RX__08: 8 PC
 SG_ P2D_BUCK_FUN_RX_Byte1_08 : 0|8@1+ (1,0) [0|255] ""  DCDC
 SG_ P2D_BUCK_FUN_RX_Byte2_08 : 8|8@1+ (1,0) [0|255] ""  DCDC
 SG_ P2D_BUCK_FUN_RX_Byte3_08 : 16|8@1+ (1,0) [0|255] ""  DCDC
 SG_ P2D_BUCK_FUN_RX_Byte4_08 : 24|8@1+ (1,0) [0|255] ""  DCDC
 SG_ P2D_BUCK_FUN_RX_Byte5_08 : 32|8@1+ (1,0) [0|255] ""  DCDC
 SG_ P2D_BUCK_FUN_RX_Byte6_08 : 40|8@1+ (1,0) [0|255] ""  DCDC
 SG_ P2D_BUCK_FUN_RX_Byte7_08 : 48|8@1+ (1,0) [0|255] ""  DCDC
 SG_ P2D_BUCK_FUN_RX_Byte8_08 : 56|8@1+ (1,0) [0|255] ""  DCDC

BO_ 2148958025 P2D_BUCK_FUN_RX__09: 8 PC
 SG_ P2D_BUCK_FUN_RX_Byte1_09 : 0|8@1+ (1,0) [0|255] ""  DCDC
 SG_ P2D_BUCK_FUN_RX_Byte2_09 : 8|8@1+ (1,0) [0|255] ""  DCDC
 SG_ P2D_BUCK_FUN_RX_Byte3_09 : 16|8@1+ (1,0) [0|255] ""  DCDC
 SG_ P2D_BUCK_FUN_RX_Byte4_09 : 24|8@1+ (1,0) [0|255] ""  DCDC
 SG_ P2D_BUCK_FUN_RX_Byte5_09 : 32|8@1+ (1,0) [0|255] ""  DCDC
 SG_ P2D_BUCK_FUN_RX_Byte6_09 : 40|8@1+ (1,0) [0|255] ""  DCDC
 SG_ P2D_BUCK_FUN_RX_Byte7_09 : 48|8@1+ (1,0) [0|255] ""  DCDC
 SG_ P2D_BUCK_FUN_RX_Byte8_09 : 56|8@1+ (1,0) [0|255] ""  DCDC

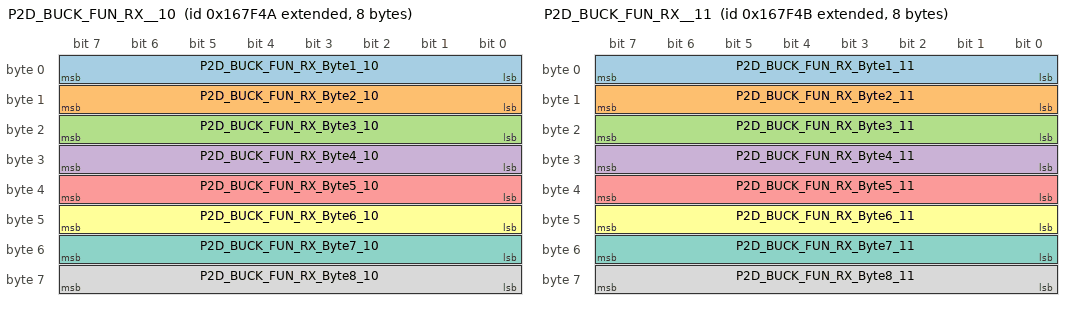
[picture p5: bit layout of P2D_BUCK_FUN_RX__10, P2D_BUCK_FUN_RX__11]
BO_ 2148958026 P2D_BUCK_FUN_RX__10: 8 PC
 SG_ P2D_BUCK_FUN_RX_Byte1_10 : 0|8@1+ (1,0) [0|255] ""  DCDC
 SG_ P2D_BUCK_FUN_RX_Byte2_10 : 8|8@1+ (1,0) [0|255] ""  DCDC
 SG_ P2D_BUCK_FUN_RX_Byte3_10 : 16|8@1+ (1,0) [0|255] ""  DCDC
 SG_ P2D_BUCK_FUN_RX_Byte4_10 : 24|8@1+ (1,0) [0|255] ""  DCDC
 SG_ P2D_BUCK_FUN_RX_Byte5_10 : 32|8@1+ (1,0) [0|255] ""  DCDC
 SG_ P2D_BUCK_FUN_RX_Byte6_10 : 40|8@1+ (1,0) [0|255] ""  DCDC
 SG_ P2D_BUCK_FUN_RX_Byte7_10 : 48|8@1+ (1,0) [0|255] ""  DCDC
 SG_ P2D_BUCK_FUN_RX_Byte8_10 : 56|8@1+ (1,0) [0|255] ""  DCDC

BO_ 2148958027 P2D_BUCK_FUN_RX__11: 8 PC
 SG_ P2D_BUCK_FUN_RX_Byte1_11 : 0|8@1+ (1,0) [0|255] ""  DCDC
 SG_ P2D_BUCK_FUN_RX_Byte2_11 : 8|8@1+ (1,0) [0|255] ""  DCDC
 SG_ P2D_BUCK_FUN_RX_Byte3_11 : 16|8@1+ (1,0) [0|255] ""  DCDC
 SG_ P2D_BUCK_FUN_RX_Byte4_11 : 24|8@1+ (1,0) [0|255] ""  DCDC
 SG_ P2D_BUCK_FUN_RX_Byte5_11 : 32|8@1+ (1,0) [0|255] ""  DCDC
 SG_ P2D_BUCK_FUN_RX_Byte6_11 : 40|8@1+ (1,0) [0|255] ""  DCDC
 SG_ P2D_BUCK_FUN_RX_Byte7_11 : 48|8@1+ (1,0) [0|255] ""  DCDC
 SG_ P2D_BUCK_FUN_RX_Byte8_11 : 56|8@1+ (1,0) [0|255] ""  DCDC

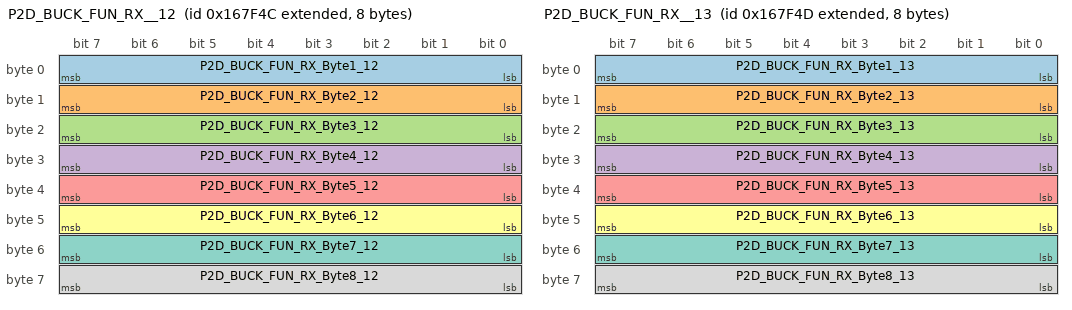
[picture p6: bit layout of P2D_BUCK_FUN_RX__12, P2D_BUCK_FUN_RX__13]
BO_ 2148958028 P2D_BUCK_FUN_RX__12: 8 PC
 SG_ P2D_BUCK_FUN_RX_Byte1_12 : 0|8@1+ (1,0) [0|255] ""  DCDC
 SG_ P2D_BUCK_FUN_RX_Byte2_12 : 8|8@1+ (1,0) [0|255] ""  DCDC
 SG_ P2D_BUCK_FUN_RX_Byte3_12 : 16|8@1+ (1,0) [0|255] ""  DCDC
 SG_ P2D_BUCK_FUN_RX_Byte4_12 : 24|8@1+ (1,0) [0|255] ""  DCDC
 SG_ P2D_BUCK_FUN_RX_Byte5_12 : 32|8@1+ (1,0) [0|255] ""  DCDC
 SG_ P2D_BUCK_FUN_RX_Byte6_12 : 40|8@1+ (1,0) [0|255] ""  DCDC
 SG_ P2D_BUCK_FUN_RX_Byte7_12 : 48|8@1+ (1,0) [0|255] ""  DCDC
 SG_ P2D_BUCK_FUN_RX_Byte8_12 : 56|8@1+ (1,0) [0|255] ""  DCDC

BO_ 2148958029 P2D_BUCK_FUN_RX__13: 8 PC
 SG_ P2D_BUCK_FUN_RX_Byte1_13 : 0|8@1+ (1,0) [0|255] ""  DCDC
 SG_ P2D_BUCK_FUN_RX_Byte2_13 : 8|8@1+ (1,0) [0|255] ""  DCDC
 SG_ P2D_BUCK_FUN_RX_Byte3_13 : 16|8@1+ (1,0) [0|255] ""  DCDC
 SG_ P2D_BUCK_FUN_RX_Byte4_13 : 24|8@1+ (1,0) [0|255] ""  DCDC
 SG_ P2D_BUCK_FUN_RX_Byte5_13 : 32|8@1+ (1,0) [0|255] ""  DCDC
 SG_ P2D_BUCK_FUN_RX_Byte6_13 : 40|8@1+ (1,0) [0|255] ""  DCDC
 SG_ P2D_BUCK_FUN_RX_Byte7_13 : 48|8@1+ (1,0) [0|255] ""  DCDC
 SG_ P2D_BUCK_FUN_RX_Byte8_13 : 56|8@1+ (1,0) [0|255] ""  DCDC

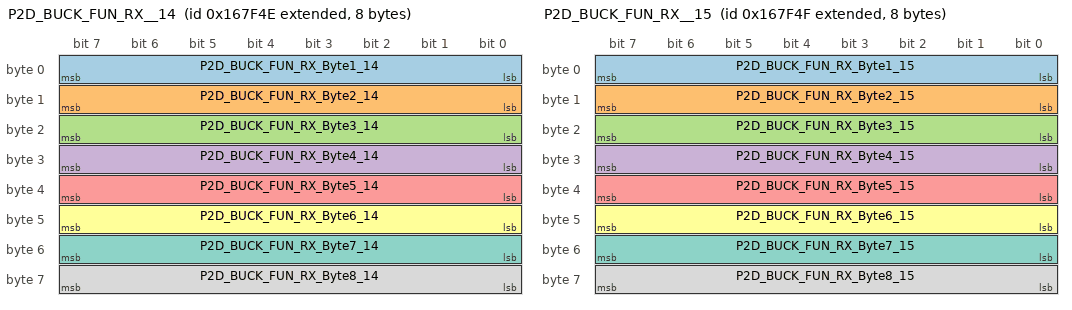
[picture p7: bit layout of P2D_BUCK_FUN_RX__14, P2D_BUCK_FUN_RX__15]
BO_ 2148958030 P2D_BUCK_FUN_RX__14: 8 PC
 SG_ P2D_BUCK_FUN_RX_Byte1_14 : 0|8@1+ (1,0) [0|255] ""  DCDC
 SG_ P2D_BUCK_FUN_RX_Byte2_14 : 8|8@1+ (1,0) [0|255] ""  DCDC
 SG_ P2D_BUCK_FUN_RX_Byte3_14 : 16|8@1+ (1,0) [0|255] ""  DCDC
 SG_ P2D_BUCK_FUN_RX_Byte4_14 : 24|8@1+ (1,0) [0|255] ""  DCDC
 SG_ P2D_BUCK_FUN_RX_Byte5_14 : 32|8@1+ (1,0) [0|255] ""  DCDC
 SG_ P2D_BUCK_FUN_RX_Byte6_14 : 40|8@1+ (1,0) [0|255] ""  DCDC
 SG_ P2D_BUCK_FUN_RX_Byte7_14 : 48|8@1+ (1,0) [0|255] ""  DCDC
 SG_ P2D_BUCK_FUN_RX_Byte8_14 : 56|8@1+ (1,0) [0|255] ""  DCDC

BO_ 2148958031 P2D_BUCK_FUN_RX__15: 8 PC
 SG_ P2D_BUCK_FUN_RX_Byte1_15 : 0|8@1+ (1,0) [0|255] ""  DCDC
 SG_ P2D_BUCK_FUN_RX_Byte2_15 : 8|8@1+ (1,0) [0|255] ""  DCDC
 SG_ P2D_BUCK_FUN_RX_Byte3_15 : 16|8@1+ (1,0) [0|255] ""  DCDC
 SG_ P2D_BUCK_FUN_RX_Byte4_15 : 24|8@1+ (1,0) [0|255] ""  DCDC
 SG_ P2D_BUCK_FUN_RX_Byte5_15 : 32|8@1+ (1,0) [0|255] ""  DCDC
 SG_ P2D_BUCK_FUN_RX_Byte6_15 : 40|8@1+ (1,0) [0|255] ""  DCDC
 SG_ P2D_BUCK_FUN_RX_Byte7_15 : 48|8@1+ (1,0) [0|255] ""  DCDC
 SG_ P2D_BUCK_FUN_RX_Byte8_15 : 56|8@1+ (1,0) [0|255] ""  DCDC

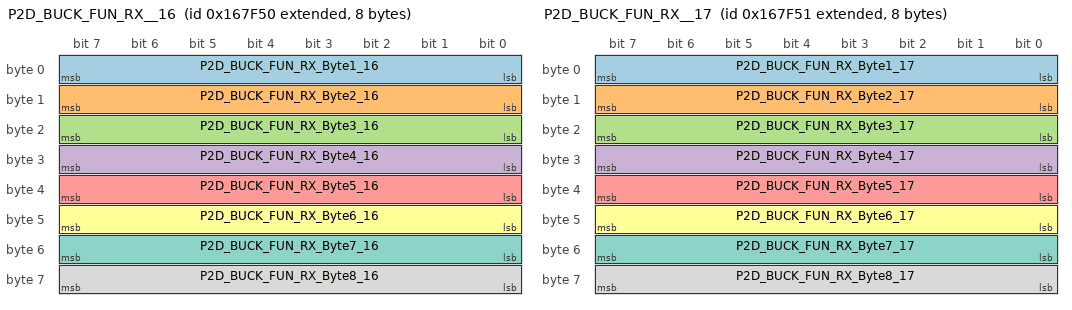
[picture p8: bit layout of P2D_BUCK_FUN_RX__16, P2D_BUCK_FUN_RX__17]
BO_ 2148958032 P2D_BUCK_FUN_RX__16: 8 PC
 SG_ P2D_BUCK_FUN_RX_Byte1_16 : 0|8@1+ (1,0) [0|255] ""  DCDC
 SG_ P2D_BUCK_FUN_RX_Byte2_16 : 8|8@1+ (1,0) [0|255] ""  DCDC
 SG_ P2D_BUCK_FUN_RX_Byte3_16 : 16|8@1+ (1,0) [0|255] ""  DCDC
 SG_ P2D_BUCK_FUN_RX_Byte4_16 : 24|8@1+ (1,0) [0|255] ""  DCDC
 SG_ P2D_BUCK_FUN_RX_Byte5_16 : 32|8@1+ (1,0) [0|255] ""  DCDC
 SG_ P2D_BUCK_FUN_RX_Byte6_16 : 40|8@1+ (1,0) [0|255] ""  DCDC
 SG_ P2D_BUCK_FUN_RX_Byte7_16 : 48|8@1+ (1,0) [0|255] ""  DCDC
 SG_ P2D_BUCK_FUN_RX_Byte8_16 : 56|8@1+ (1,0) [0|255] ""  DCDC

BO_ 2148958033 P2D_BUCK_FUN_RX__17: 8 PC
 SG_ P2D_BUCK_FUN_RX_Byte1_17 : 0|8@1+ (1,0) [0|255] ""  DCDC
 SG_ P2D_BUCK_FUN_RX_Byte2_17 : 8|8@1+ (1,0) [0|255] ""  DCDC
 SG_ P2D_BUCK_FUN_RX_Byte3_17 : 16|8@1+ (1,0) [0|255] ""  DCDC
 SG_ P2D_BUCK_FUN_RX_Byte4_17 : 24|8@1+ (1,0) [0|255] ""  DCDC
 SG_ P2D_BUCK_FUN_RX_Byte5_17 : 32|8@1+ (1,0) [0|255] ""  DCDC
 SG_ P2D_BUCK_FUN_RX_Byte6_17 : 40|8@1+ (1,0) [0|255] ""  DCDC
 SG_ P2D_BUCK_FUN_RX_Byte7_17 : 48|8@1+ (1,0) [0|255] ""  DCDC
 SG_ P2D_BUCK_FUN_RX_Byte8_17 : 56|8@1+ (1,0) [0|255] ""  DCDC

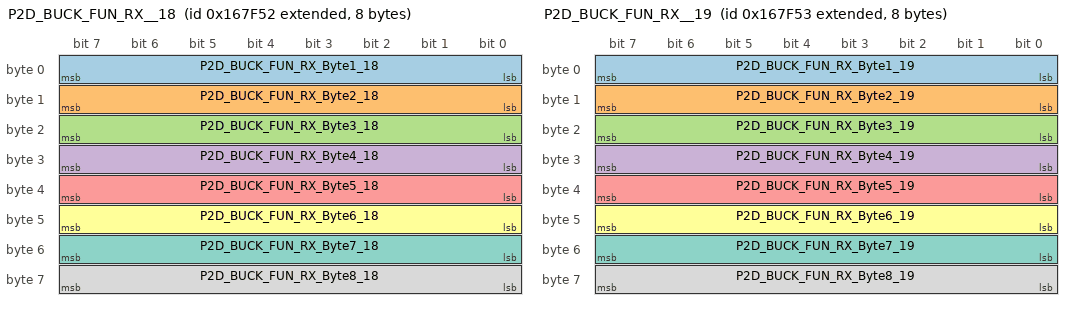
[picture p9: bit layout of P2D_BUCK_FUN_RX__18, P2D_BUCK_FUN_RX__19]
BO_ 2148958034 P2D_BUCK_FUN_RX__18: 8 PC
 SG_ P2D_BUCK_FUN_RX_Byte1_18 : 0|8@1+ (1,0) [0|255] ""  DCDC
 SG_ P2D_BUCK_FUN_RX_Byte2_18 : 8|8@1+ (1,0) [0|255] ""  DCDC
 SG_ P2D_BUCK_FUN_RX_Byte3_18 : 16|8@1+ (1,0) [0|255] ""  DCDC
 SG_ P2D_BUCK_FUN_RX_Byte4_18 : 24|8@1+ (1,0) [0|255] ""  DCDC
 SG_ P2D_BUCK_FUN_RX_Byte5_18 : 32|8@1+ (1,0) [0|255] ""  DCDC
 SG_ P2D_BUCK_FUN_RX_Byte6_18 : 40|8@1+ (1,0) [0|255] ""  DCDC
 SG_ P2D_BUCK_FUN_RX_Byte7_18 : 48|8@1+ (1,0) [0|255] ""  DCDC
 SG_ P2D_BUCK_FUN_RX_Byte8_18 : 56|8@1+ (1,0) [0|255] ""  DCDC

BO_ 2148958035 P2D_BUCK_FUN_RX__19: 8 PC
 SG_ P2D_BUCK_FUN_RX_Byte1_19 : 0|8@1+ (1,0) [0|255] ""  DCDC
 SG_ P2D_BUCK_FUN_RX_Byte2_19 : 8|8@1+ (1,0) [0|255] ""  DCDC
 SG_ P2D_BUCK_FUN_RX_Byte3_19 : 16|8@1+ (1,0) [0|255] ""  DCDC
 SG_ P2D_BUCK_FUN_RX_Byte4_19 : 24|8@1+ (1,0) [0|255] ""  DCDC
 SG_ P2D_BUCK_FUN_RX_Byte5_19 : 32|8@1+ (1,0) [0|255] ""  DCDC
 SG_ P2D_BUCK_FUN_RX_Byte6_19 : 40|8@1+ (1,0) [0|255] ""  DCDC
 SG_ P2D_BUCK_FUN_RX_Byte7_19 : 48|8@1+ (1,0) [0|255] ""  DCDC
 SG_ P2D_BUCK_FUN_RX_Byte8_19 : 56|8@1+ (1,0) [0|255] ""  DCDC

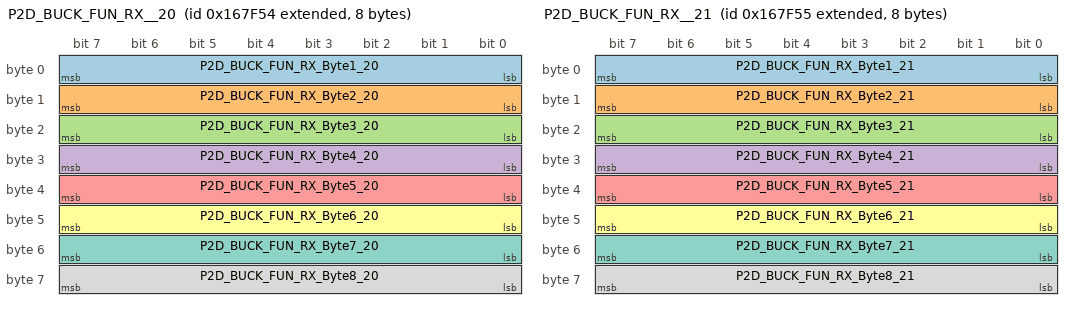
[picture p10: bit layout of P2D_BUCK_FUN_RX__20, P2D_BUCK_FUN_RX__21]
BO_ 2148958036 P2D_BUCK_FUN_RX__20: 8 PC
 SG_ P2D_BUCK_FUN_RX_Byte1_20 : 0|8@1+ (1,0) [0|255] ""  DCDC
 SG_ P2D_BUCK_FUN_RX_Byte2_20 : 8|8@1+ (1,0) [0|255] ""  DCDC
 SG_ P2D_BUCK_FUN_RX_Byte3_20 : 16|8@1+ (1,0) [0|255] ""  DCDC
 SG_ P2D_BUCK_FUN_RX_Byte4_20 : 24|8@1+ (1,0) [0|255] ""  DCDC
 SG_ P2D_BUCK_FUN_RX_Byte5_20 : 32|8@1+ (1,0) [0|255] ""  DCDC
 SG_ P2D_BUCK_FUN_RX_Byte6_20 : 40|8@1+ (1,0) [0|255] ""  DCDC
 SG_ P2D_BUCK_FUN_RX_Byte7_20 : 48|8@1+ (1,0) [0|255] ""  DCDC
 SG_ P2D_BUCK_FUN_RX_Byte8_20 : 56|8@1+ (1,0) [0|255] ""  DCDC

BO_ 2148958037 P2D_BUCK_FUN_RX__21: 8 PC
 SG_ P2D_BUCK_FUN_RX_Byte1_21 : 0|8@1+ (1,0) [0|255] ""  DCDC
 SG_ P2D_BUCK_FUN_RX_Byte2_21 : 8|8@1+ (1,0) [0|255] ""  DCDC
 SG_ P2D_BUCK_FUN_RX_Byte3_21 : 16|8@1+ (1,0) [0|255] ""  DCDC
 SG_ P2D_BUCK_FUN_RX_Byte4_21 : 24|8@1+ (1,0) [0|255] ""  DCDC
 SG_ P2D_BUCK_FUN_RX_Byte5_21 : 32|8@1+ (1,0) [0|255] ""  DCDC
 SG_ P2D_BUCK_FUN_RX_Byte6_21 : 40|8@1+ (1,0) [0|255] ""  DCDC
 SG_ P2D_BUCK_FUN_RX_Byte7_21 : 48|8@1+ (1,0) [0|255] ""  DCDC
 SG_ P2D_BUCK_FUN_RX_Byte8_21 : 56|8@1+ (1,0) [0|255] ""  DCDC

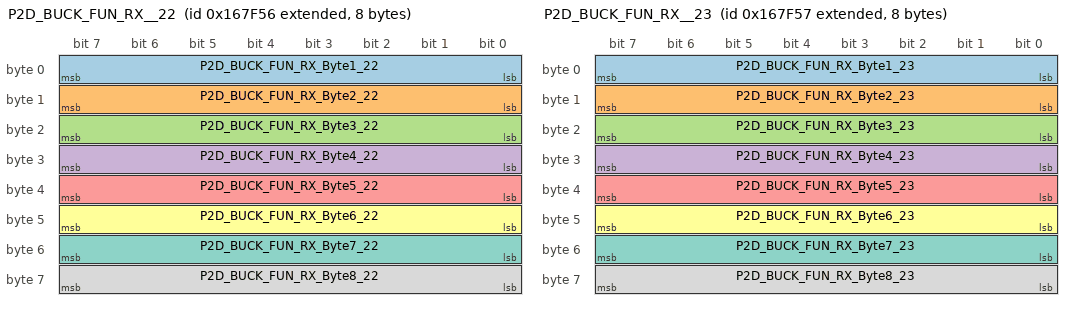
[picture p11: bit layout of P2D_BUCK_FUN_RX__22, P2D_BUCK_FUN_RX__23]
BO_ 2148958038 P2D_BUCK_FUN_RX__22: 8 PC
 SG_ P2D_BUCK_FUN_RX_Byte1_22 : 0|8@1+ (1,0) [0|255] ""  DCDC
 SG_ P2D_BUCK_FUN_RX_Byte2_22 : 8|8@1+ (1,0) [0|255] ""  DCDC
 SG_ P2D_BUCK_FUN_RX_Byte3_22 : 16|8@1+ (1,0) [0|255] ""  DCDC
 SG_ P2D_BUCK_FUN_RX_Byte4_22 : 24|8@1+ (1,0) [0|255] ""  DCDC
 SG_ P2D_BUCK_FUN_RX_Byte5_22 : 32|8@1+ (1,0) [0|255] ""  DCDC
 SG_ P2D_BUCK_FUN_RX_Byte6_22 : 40|8@1+ (1,0) [0|255] ""  DCDC
 SG_ P2D_BUCK_FUN_RX_Byte7_22 : 48|8@1+ (1,0) [0|255] ""  DCDC
 SG_ P2D_BUCK_FUN_RX_Byte8_22 : 56|8@1+ (1,0) [0|255] ""  DCDC

BO_ 2148958039 P2D_BUCK_FUN_RX__23: 8 PC
 SG_ P2D_BUCK_FUN_RX_Byte1_23 : 0|8@1+ (1,0) [0|255] ""  DCDC
 SG_ P2D_BUCK_FUN_RX_Byte2_23 : 8|8@1+ (1,0) [0|255] ""  DCDC
 SG_ P2D_BUCK_FUN_RX_Byte3_23 : 16|8@1+ (1,0) [0|255] ""  DCDC
 SG_ P2D_BUCK_FUN_RX_Byte4_23 : 24|8@1+ (1,0) [0|255] ""  DCDC
 SG_ P2D_BUCK_FUN_RX_Byte5_23 : 32|8@1+ (1,0) [0|255] ""  DCDC
 SG_ P2D_BUCK_FUN_RX_Byte6_23 : 40|8@1+ (1,0) [0|255] ""  DCDC
 SG_ P2D_BUCK_FUN_RX_Byte7_23 : 48|8@1+ (1,0) [0|255] ""  DCDC
 SG_ P2D_BUCK_FUN_RX_Byte8_23 : 56|8@1+ (1,0) [0|255] ""  DCDC

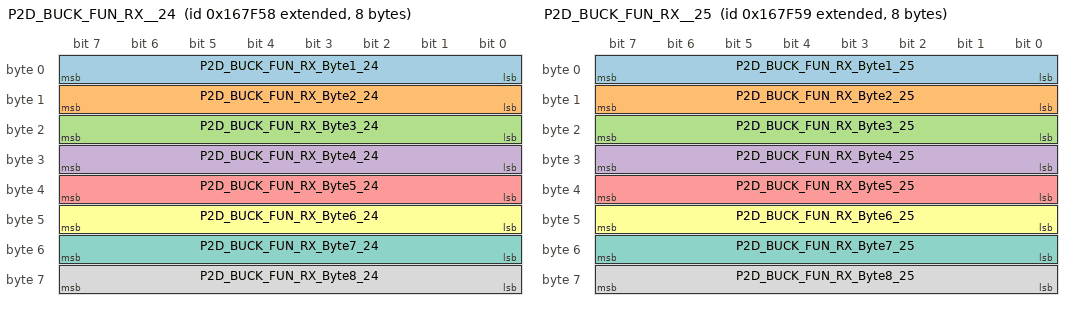
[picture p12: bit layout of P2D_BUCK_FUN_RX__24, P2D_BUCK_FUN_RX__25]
BO_ 2148958040 P2D_BUCK_FUN_RX__24: 8 PC
 SG_ P2D_BUCK_FUN_RX_Byte1_24 : 0|8@1+ (1,0) [0|255] ""  DCDC
 SG_ P2D_BUCK_FUN_RX_Byte2_24 : 8|8@1+ (1,0) [0|255] ""  DCDC
 SG_ P2D_BUCK_FUN_RX_Byte3_24 : 16|8@1+ (1,0) [0|255] ""  DCDC
 SG_ P2D_BUCK_FUN_RX_Byte4_24 : 24|8@1+ (1,0) [0|255] ""  DCDC
 SG_ P2D_BUCK_FUN_RX_Byte5_24 : 32|8@1+ (1,0) [0|255] ""  DCDC
 SG_ P2D_BUCK_FUN_RX_Byte6_24 : 40|8@1+ (1,0) [0|255] ""  DCDC
 SG_ P2D_BUCK_FUN_RX_Byte7_24 : 48|8@1+ (1,0) [0|255] ""  DCDC
 SG_ P2D_BUCK_FUN_RX_Byte8_24 : 56|8@1+ (1,0) [0|255] ""  DCDC

BO_ 2148958041 P2D_BUCK_FUN_RX__25: 8 PC
 SG_ P2D_BUCK_FUN_RX_Byte1_25 : 0|8@1+ (1,0) [0|255] ""  DCDC
 SG_ P2D_BUCK_FUN_RX_Byte2_25 : 8|8@1+ (1,0) [0|255] ""  DCDC
 SG_ P2D_BUCK_FUN_RX_Byte3_25 : 16|8@1+ (1,0) [0|255] ""  DCDC
 SG_ P2D_BUCK_FUN_RX_Byte4_25 : 24|8@1+ (1,0) [0|255] ""  DCDC
 SG_ P2D_BUCK_FUN_RX_Byte5_25 : 32|8@1+ (1,0) [0|255] ""  DCDC
 SG_ P2D_BUCK_FUN_RX_Byte6_25 : 40|8@1+ (1,0) [0|255] ""  DCDC
 SG_ P2D_BUCK_FUN_RX_Byte7_25 : 48|8@1+ (1,0) [0|255] ""  DCDC
 SG_ P2D_BUCK_FUN_RX_Byte8_25 : 56|8@1+ (1,0) [0|255] ""  DCDC

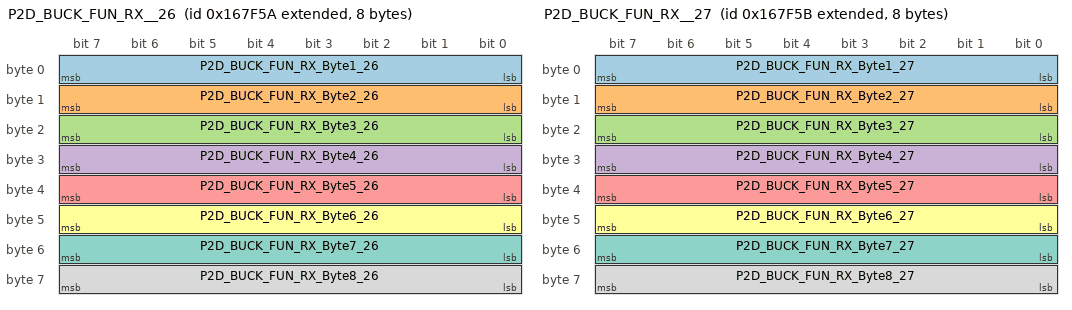
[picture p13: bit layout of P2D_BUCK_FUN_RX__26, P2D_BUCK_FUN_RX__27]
BO_ 2148958042 P2D_BUCK_FUN_RX__26: 8 PC
 SG_ P2D_BUCK_FUN_RX_Byte1_26 : 0|8@1+ (1,0) [0|255] ""  DCDC
 SG_ P2D_BUCK_FUN_RX_Byte2_26 : 8|8@1+ (1,0) [0|255] ""  DCDC
 SG_ P2D_BUCK_FUN_RX_Byte3_26 : 16|8@1+ (1,0) [0|255] ""  DCDC
 SG_ P2D_BUCK_FUN_RX_Byte4_26 : 24|8@1+ (1,0) [0|255] ""  DCDC
 SG_ P2D_BUCK_FUN_RX_Byte5_26 : 32|8@1+ (1,0) [0|255] ""  DCDC
 SG_ P2D_BUCK_FUN_RX_Byte6_26 : 40|8@1+ (1,0) [0|255] ""  DCDC
 SG_ P2D_BUCK_FUN_RX_Byte7_26 : 48|8@1+ (1,0) [0|255] ""  DCDC
 SG_ P2D_BUCK_FUN_RX_Byte8_26 : 56|8@1+ (1,0) [0|255] ""  DCDC

BO_ 2148958043 P2D_BUCK_FUN_RX__27: 8 PC
 SG_ P2D_BUCK_FUN_RX_Byte1_27 : 0|8@1+ (1,0) [0|255] ""  DCDC
 SG_ P2D_BUCK_FUN_RX_Byte2_27 : 8|8@1+ (1,0) [0|255] ""  DCDC
 SG_ P2D_BUCK_FUN_RX_Byte3_27 : 16|8@1+ (1,0) [0|255] ""  DCDC
 SG_ P2D_BUCK_FUN_RX_Byte4_27 : 24|8@1+ (1,0) [0|255] ""  DCDC
 SG_ P2D_BUCK_FUN_RX_Byte5_27 : 32|8@1+ (1,0) [0|255] ""  DCDC
 SG_ P2D_BUCK_FUN_RX_Byte6_27 : 40|8@1+ (1,0) [0|255] ""  DCDC
 SG_ P2D_BUCK_FUN_RX_Byte7_27 : 48|8@1+ (1,0) [0|255] ""  DCDC
 SG_ P2D_BUCK_FUN_RX_Byte8_27 : 56|8@1+ (1,0) [0|255] ""  DCDC

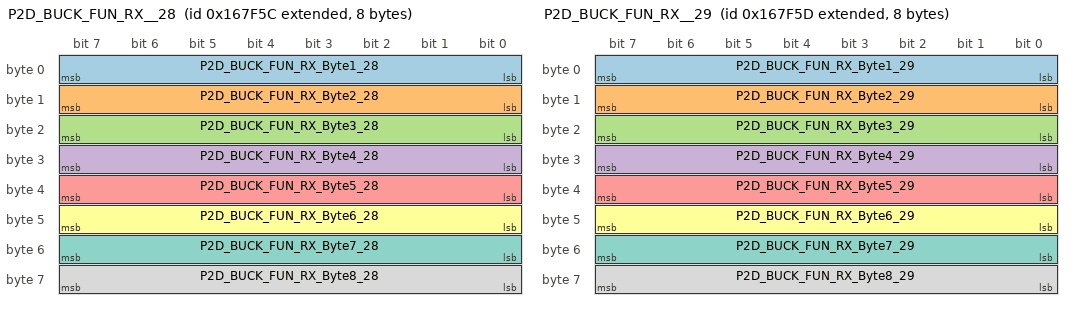
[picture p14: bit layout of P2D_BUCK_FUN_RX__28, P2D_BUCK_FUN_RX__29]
BO_ 2148958044 P2D_BUCK_FUN_RX__28: 8 PC
 SG_ P2D_BUCK_FUN_RX_Byte1_28 : 0|8@1+ (1,0) [0|255] ""  DCDC
 SG_ P2D_BUCK_FUN_RX_Byte2_28 : 8|8@1+ (1,0) [0|255] ""  DCDC
 SG_ P2D_BUCK_FUN_RX_Byte3_28 : 16|8@1+ (1,0) [0|255] ""  DCDC
 SG_ P2D_BUCK_FUN_RX_Byte4_28 : 24|8@1+ (1,0) [0|255] ""  DCDC
 SG_ P2D_BUCK_FUN_RX_Byte5_28 : 32|8@1+ (1,0) [0|255] ""  DCDC
 SG_ P2D_BUCK_FUN_RX_Byte6_28 : 40|8@1+ (1,0) [0|255] ""  DCDC
 SG_ P2D_BUCK_FUN_RX_Byte7_28 : 48|8@1+ (1,0) [0|255] ""  DCDC
 SG_ P2D_BUCK_FUN_RX_Byte8_28 : 56|8@1+ (1,0) [0|255] ""  DCDC

BO_ 2148958045 P2D_BUCK_FUN_RX__29: 8 PC
 SG_ P2D_BUCK_FUN_RX_Byte1_29 : 0|8@1+ (1,0) [0|255] ""  DCDC
 SG_ P2D_BUCK_FUN_RX_Byte2_29 : 8|8@1+ (1,0) [0|255] ""  DCDC
 SG_ P2D_BUCK_FUN_RX_Byte3_29 : 16|8@1+ (1,0) [0|255] ""  DCDC
 SG_ P2D_BUCK_FUN_RX_Byte4_29 : 24|8@1+ (1,0) [0|255] ""  DCDC
 SG_ P2D_BUCK_FUN_RX_Byte5_29 : 32|8@1+ (1,0) [0|255] ""  DCDC
 SG_ P2D_BUCK_FUN_RX_Byte6_29 : 40|8@1+ (1,0) [0|255] ""  DCDC
 SG_ P2D_BUCK_FUN_RX_Byte7_29 : 48|8@1+ (1,0) [0|255] ""  DCDC
 SG_ P2D_BUCK_FUN_RX_Byte8_29 : 56|8@1+ (1,0) [0|255] ""  DCDC

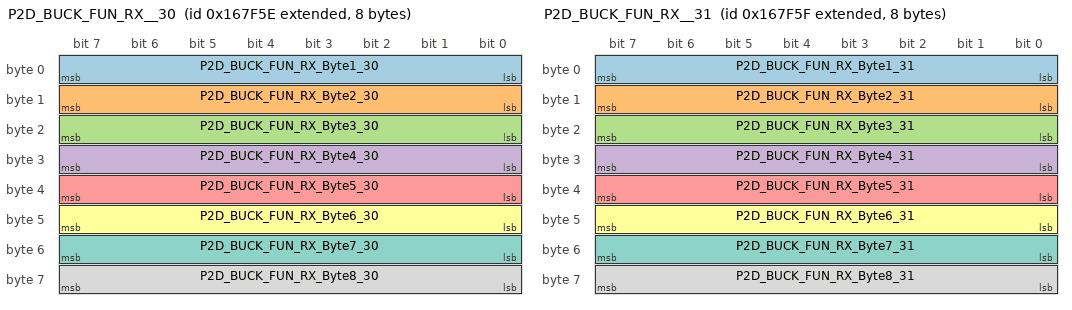
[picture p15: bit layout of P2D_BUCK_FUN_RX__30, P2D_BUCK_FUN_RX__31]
BO_ 2148958046 P2D_BUCK_FUN_RX__30: 8 PC
 SG_ P2D_BUCK_FUN_RX_Byte1_30 : 0|8@1+ (1,0) [0|255] ""  DCDC
 SG_ P2D_BUCK_FUN_RX_Byte2_30 : 8|8@1+ (1,0) [0|255] ""  DCDC
 SG_ P2D_BUCK_FUN_RX_Byte3_30 : 16|8@1+ (1,0) [0|255] ""  DCDC
 SG_ P2D_BUCK_FUN_RX_Byte4_30 : 24|8@1+ (1,0) [0|255] ""  DCDC
 SG_ P2D_BUCK_FUN_RX_Byte5_30 : 32|8@1+ (1,0) [0|255] ""  DCDC
 SG_ P2D_BUCK_FUN_RX_Byte6_30 : 40|8@1+ (1,0) [0|255] ""  DCDC
 SG_ P2D_BUCK_FUN_RX_Byte7_30 : 48|8@1+ (1,0) [0|255] ""  DCDC
 SG_ P2D_BUCK_FUN_RX_Byte8_30 : 56|8@1+ (1,0) [0|255] ""  DCDC

BO_ 2148958047 P2D_BUCK_FUN_RX__31: 8 PC
 SG_ P2D_BUCK_FUN_RX_Byte1_31 : 0|8@1+ (1,0) [0|255] ""  DCDC
 SG_ P2D_BUCK_FUN_RX_Byte2_31 : 8|8@1+ (1,0) [0|255] ""  DCDC
 SG_ P2D_BUCK_FUN_RX_Byte3_31 : 16|8@1+ (1,0) [0|255] ""  DCDC
 SG_ P2D_BUCK_FUN_RX_Byte4_31 : 24|8@1+ (1,0) [0|255] ""  DCDC
 SG_ P2D_BUCK_FUN_RX_Byte5_31 : 32|8@1+ (1,0) [0|255] ""  DCDC
 SG_ P2D_BUCK_FUN_RX_Byte6_31 : 40|8@1+ (1,0) [0|255] ""  DCDC
 SG_ P2D_BUCK_FUN_RX_Byte7_31 : 48|8@1+ (1,0) [0|255] ""  DCDC
 SG_ P2D_BUCK_FUN_RX_Byte8_31 : 56|8@1+ (1,0) [0|255] ""  DCDC

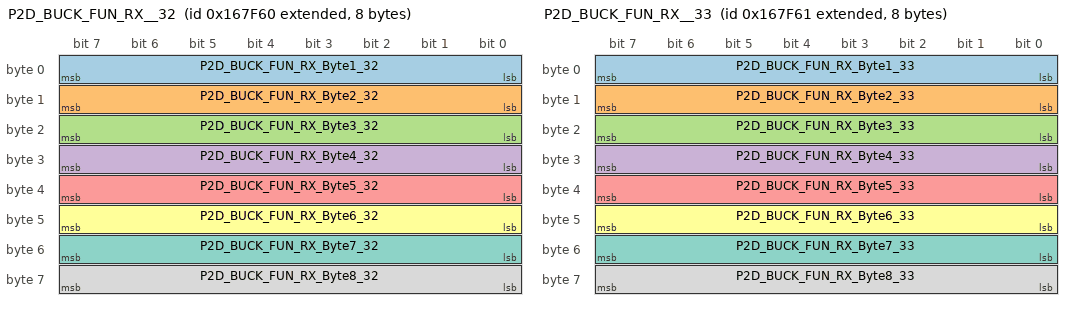
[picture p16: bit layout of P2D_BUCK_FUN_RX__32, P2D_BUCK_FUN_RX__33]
BO_ 2148958048 P2D_BUCK_FUN_RX__32: 8 PC
 SG_ P2D_BUCK_FUN_RX_Byte1_32 : 0|8@1+ (1,0) [0|255] ""  DCDC
 SG_ P2D_BUCK_FUN_RX_Byte2_32 : 8|8@1+ (1,0) [0|255] ""  DCDC
 SG_ P2D_BUCK_FUN_RX_Byte3_32 : 16|8@1+ (1,0) [0|255] ""  DCDC
 SG_ P2D_BUCK_FUN_RX_Byte4_32 : 24|8@1+ (1,0) [0|255] ""  DCDC
 SG_ P2D_BUCK_FUN_RX_Byte5_32 : 32|8@1+ (1,0) [0|255] ""  DCDC
 SG_ P2D_BUCK_FUN_RX_Byte6_32 : 40|8@1+ (1,0) [0|255] ""  DCDC
 SG_ P2D_BUCK_FUN_RX_Byte7_32 : 48|8@1+ (1,0) [0|255] ""  DCDC
 SG_ P2D_BUCK_FUN_RX_Byte8_32 : 56|8@1+ (1,0) [0|255] ""  DCDC

BO_ 2148958049 P2D_BUCK_FUN_RX__33: 8 PC
 SG_ P2D_BUCK_FUN_RX_Byte1_33 : 0|8@1+ (1,0) [0|255] ""  DCDC
 SG_ P2D_BUCK_FUN_RX_Byte2_33 : 8|8@1+ (1,0) [0|255] ""  DCDC
 SG_ P2D_BUCK_FUN_RX_Byte3_33 : 16|8@1+ (1,0) [0|255] ""  DCDC
 SG_ P2D_BUCK_FUN_RX_Byte4_33 : 24|8@1+ (1,0) [0|255] ""  DCDC
 SG_ P2D_BUCK_FUN_RX_Byte5_33 : 32|8@1+ (1,0) [0|255] ""  DCDC
 SG_ P2D_BUCK_FUN_RX_Byte6_33 : 40|8@1+ (1,0) [0|255] ""  DCDC
 SG_ P2D_BUCK_FUN_RX_Byte7_33 : 48|8@1+ (1,0) [0|255] ""  DCDC
 SG_ P2D_BUCK_FUN_RX_Byte8_33 : 56|8@1+ (1,0) [0|255] ""  DCDC

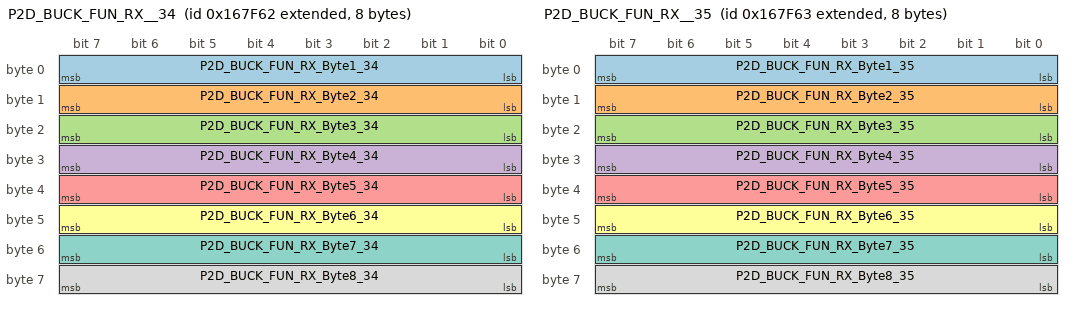
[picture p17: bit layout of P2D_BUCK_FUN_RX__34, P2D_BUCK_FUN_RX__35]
BO_ 2148958050 P2D_BUCK_FUN_RX__34: 8 PC
 SG_ P2D_BUCK_FUN_RX_Byte1_34 : 0|8@1+ (1,0) [0|255] ""  DCDC
 SG_ P2D_BUCK_FUN_RX_Byte2_34 : 8|8@1+ (1,0) [0|255] ""  DCDC
 SG_ P2D_BUCK_FUN_RX_Byte3_34 : 16|8@1+ (1,0) [0|255] ""  DCDC
 SG_ P2D_BUCK_FUN_RX_Byte4_34 : 24|8@1+ (1,0) [0|255] ""  DCDC
 SG_ P2D_BUCK_FUN_RX_Byte5_34 : 32|8@1+ (1,0) [0|255] ""  DCDC
 SG_ P2D_BUCK_FUN_RX_Byte6_34 : 40|8@1+ (1,0) [0|255] ""  DCDC
 SG_ P2D_BUCK_FUN_RX_Byte7_34 : 48|8@1+ (1,0) [0|255] ""  DCDC
 SG_ P2D_BUCK_FUN_RX_Byte8_34 : 56|8@1+ (1,0) [0|255] ""  DCDC

BO_ 2148958051 P2D_BUCK_FUN_RX__35: 8 PC
 SG_ P2D_BUCK_FUN_RX_Byte1_35 : 0|8@1+ (1,0) [0|255] ""  DCDC
 SG_ P2D_BUCK_FUN_RX_Byte2_35 : 8|8@1+ (1,0) [0|255] ""  DCDC
 SG_ P2D_BUCK_FUN_RX_Byte3_35 : 16|8@1+ (1,0) [0|255] ""  DCDC
 SG_ P2D_BUCK_FUN_RX_Byte4_35 : 24|8@1+ (1,0) [0|255] ""  DCDC
 SG_ P2D_BUCK_FUN_RX_Byte5_35 : 32|8@1+ (1,0) [0|255] ""  DCDC
 SG_ P2D_BUCK_FUN_RX_Byte6_35 : 40|8@1+ (1,0) [0|255] ""  DCDC
 SG_ P2D_BUCK_FUN_RX_Byte7_35 : 48|8@1+ (1,0) [0|255] ""  DCDC
 SG_ P2D_BUCK_FUN_RX_Byte8_35 : 56|8@1+ (1,0) [0|255] ""  DCDC

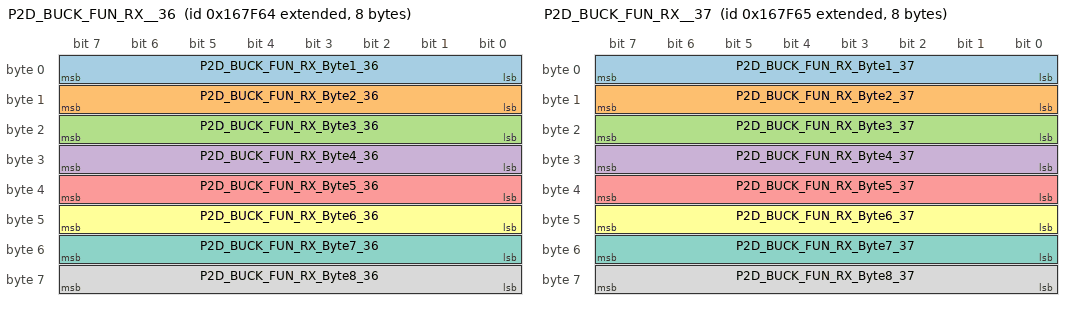
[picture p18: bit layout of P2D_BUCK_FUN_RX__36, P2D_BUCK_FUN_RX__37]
BO_ 2148958052 P2D_BUCK_FUN_RX__36: 8 PC
 SG_ P2D_BUCK_FUN_RX_Byte1_36 : 0|8@1+ (1,0) [0|255] ""  DCDC
 SG_ P2D_BUCK_FUN_RX_Byte2_36 : 8|8@1+ (1,0) [0|255] ""  DCDC
 SG_ P2D_BUCK_FUN_RX_Byte3_36 : 16|8@1+ (1,0) [0|255] ""  DCDC
 SG_ P2D_BUCK_FUN_RX_Byte4_36 : 24|8@1+ (1,0) [0|255] ""  DCDC
 SG_ P2D_BUCK_FUN_RX_Byte5_36 : 32|8@1+ (1,0) [0|255] ""  DCDC
 SG_ P2D_BUCK_FUN_RX_Byte6_36 : 40|8@1+ (1,0) [0|255] ""  DCDC
 SG_ P2D_BUCK_FUN_RX_Byte7_36 : 48|8@1+ (1,0) [0|255] ""  DCDC
 SG_ P2D_BUCK_FUN_RX_Byte8_36 : 56|8@1+ (1,0) [0|255] ""  DCDC

BO_ 2148958053 P2D_BUCK_FUN_RX__37: 8 PC
 SG_ P2D_BUCK_FUN_RX_Byte1_37 : 0|8@1+ (1,0) [0|255] ""  DCDC
 SG_ P2D_BUCK_FUN_RX_Byte2_37 : 8|8@1+ (1,0) [0|255] ""  DCDC
 SG_ P2D_BUCK_FUN_RX_Byte3_37 : 16|8@1+ (1,0) [0|255] ""  DCDC
 SG_ P2D_BUCK_FUN_RX_Byte4_37 : 24|8@1+ (1,0) [0|255] ""  DCDC
 SG_ P2D_BUCK_FUN_RX_Byte5_37 : 32|8@1+ (1,0) [0|255] ""  DCDC
 SG_ P2D_BUCK_FUN_RX_Byte6_37 : 40|8@1+ (1,0) [0|255] ""  DCDC
 SG_ P2D_BUCK_FUN_RX_Byte7_37 : 48|8@1+ (1,0) [0|255] ""  DCDC
 SG_ P2D_BUCK_FUN_RX_Byte8_37 : 56|8@1+ (1,0) [0|255] ""  DCDC

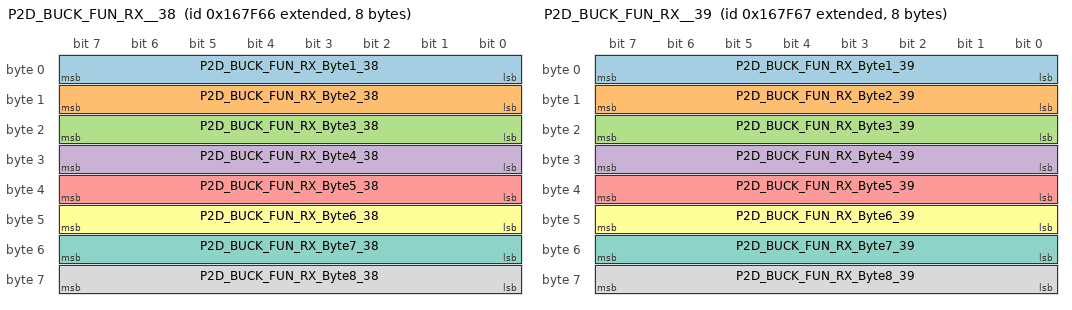
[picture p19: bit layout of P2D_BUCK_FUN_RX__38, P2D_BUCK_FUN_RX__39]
BO_ 2148958054 P2D_BUCK_FUN_RX__38: 8 PC
 SG_ P2D_BUCK_FUN_RX_Byte1_38 : 0|8@1+ (1,0) [0|255] ""  DCDC
 SG_ P2D_BUCK_FUN_RX_Byte2_38 : 8|8@1+ (1,0) [0|255] ""  DCDC
 SG_ P2D_BUCK_FUN_RX_Byte3_38 : 16|8@1+ (1,0) [0|255] ""  DCDC
 SG_ P2D_BUCK_FUN_RX_Byte4_38 : 24|8@1+ (1,0) [0|255] ""  DCDC
 SG_ P2D_BUCK_FUN_RX_Byte5_38 : 32|8@1+ (1,0) [0|255] ""  DCDC
 SG_ P2D_BUCK_FUN_RX_Byte6_38 : 40|8@1+ (1,0) [0|255] ""  DCDC
 SG_ P2D_BUCK_FUN_RX_Byte7_38 : 48|8@1+ (1,0) [0|255] ""  DCDC
 SG_ P2D_BUCK_FUN_RX_Byte8_38 : 56|8@1+ (1,0) [0|255] ""  DCDC

BO_ 2148958055 P2D_BUCK_FUN_RX__39: 8 PC
 SG_ P2D_BUCK_FUN_RX_Byte1_39 : 0|8@1+ (1,0) [0|255] ""  DCDC
 SG_ P2D_BUCK_FUN_RX_Byte2_39 : 8|8@1+ (1,0) [0|255] ""  DCDC
 SG_ P2D_BUCK_FUN_RX_Byte3_39 : 16|8@1+ (1,0) [0|255] ""  DCDC
 SG_ P2D_BUCK_FUN_RX_Byte4_39 : 24|8@1+ (1,0) [0|255] ""  DCDC
 SG_ P2D_BUCK_FUN_RX_Byte5_39 : 32|8@1+ (1,0) [0|255] ""  DCDC
 SG_ P2D_BUCK_FUN_RX_Byte6_39 : 40|8@1+ (1,0) [0|255] ""  DCDC
 SG_ P2D_BUCK_FUN_RX_Byte7_39 : 48|8@1+ (1,0) [0|255] ""  DCDC
 SG_ P2D_BUCK_FUN_RX_Byte8_39 : 56|8@1+ (1,0) [0|255] ""  DCDC

BO_ 2148958056 P2D_BUCK_FUN_RX__40: 8 PC
 SG_ P2D_BUCK_FUN_RX_Byte1_40 : 0|8@1+ (1,0) [0|255] ""  DCDC
 SG_ P2D_BUCK_FUN_RX_Byte2_40 : 8|8@1+ (1,0) [0|255] ""  DCDC
 SG_ P2D_BUCK_FUN_RX_Byte3_40 : 16|8@1+ (1,0) [0|255] ""  DCDC
 SG_ P2D_BUCK_FUN_RX_Byte4_40 : 24|8@1+ (1,0) [0|255] ""  DCDC
 SG_ P2D_BUCK_FUN_RX_Byte5_40 : 32|8@1+ (1,0) [0|255] ""  DCDC
 SG_ P2D_BUCK_FUN_RX_Byte6_40 : 40|8@1+ (1,0) [0|255] ""  DCDC
 SG_ P2D_BUCK_FUN_RX_Byte7_40 : 48|8@1+ (1,0) [0|255] ""  DCDC
 SG_ P2D_BUCK_FUN_RX_Byte8_40 : 56|8@1+ (1,0) [0|255] ""  DCDC

BO_ 2148958057 P2D_BUCK_FUN_RX__41: 8 PC
 SG_ P2D_BUCK_FUN_RX_Byte1_41 : 0|8@1+ (1,0) [0|255] ""  DCDC
 SG_ P2D_BUCK_FUN_RX_Byte2_41 : 8|8@1+ (1,0) [0|255] ""  DCDC
 SG_ P2D_BUCK_FUN_RX_Byte3_41 : 16|8@1+ (1,0) [0|255] ""  DCDC
 SG_ P2D_BUCK_FUN_RX_Byte4_41 : 24|8@1+ (1,0) [0|255] ""  DCDC
 SG_ P2D_BUCK_FUN_RX_Byte5_41 : 32|8@1+ (1,0) [0|255] ""  DCDC
 SG_ P2D_BUCK_FUN_RX_Byte6_41 : 40|8@1+ (1,0) [0|255] ""  DCDC
 SG_ P2D_BUCK_FUN_RX_Byte7_41 : 48|8@1+ (1,0) [0|255] ""  DCDC
 SG_ P2D_BUCK_FUN_RX_Byte8_41 : 56|8@1+ (1,0) [0|255] ""  DCDC

BO_ 2148958058 P2D_BUCK_FUN_RX__42: 8 PC
 SG_ P2D_BUCK_FUN_RX_Byte1_42 : 0|8@1+ (1,0) [0|255] ""  DCDC
 SG_ P2D_BUCK_FUN_RX_Byte2_42 : 8|8@1+ (1,0) [0|255] ""  DCDC
 SG_ P2D_BUCK_FUN_RX_Byte3_42 : 16|8@1+ (1,0) [0|255] ""  DCDC
 SG_ P2D_BUCK_FUN_RX_Byte4_42 : 24|8@1+ (1,0) [0|255] ""  DCDC
 SG_ P2D_BUCK_FUN_RX_Byte5_42 : 32|8@1+ (1,0) [0|255] ""  DCDC
 SG_ P2D_BUCK_FUN_RX_Byte6_42 : 40|8@1+ (1,0) [0|255] ""  DCDC
 SG_ P2D_BUCK_FUN_RX_Byte7_42 : 48|8@1+ (1,0) [0|255] ""  DCDC
 SG_ P2D_BUCK_FUN_RX_Byte8_42 : 56|8@1+ (1,0) [0|255] ""  DCDC

BO_ 2148958059 P2D_BUCK_FUN_RX__43: 8 PC
 SG_ P2D_BUCK_FUN_RX_Byte1_43 : 0|8@1+ (1,0) [0|255] ""  DCDC
 SG_ P2D_BUCK_FUN_RX_Byte2_43 : 8|8@1+ (1,0) [0|255] ""  DCDC
 SG_ P2D_BUCK_FUN_RX_Byte3_43 : 16|8@1+ (1,0) [0|255] ""  DCDC
 SG_ P2D_BUCK_FUN_RX_Byte4_43 : 24|8@1+ (1,0) [0|255] ""  DCDC
 SG_ P2D_BUCK_FUN_RX_Byte5_43 : 32|8@1+ (1,0) [0|255] ""  DCDC
 SG_ P2D_BUCK_FUN_RX_Byte6_43 : 40|8@1+ (1,0) [0|255] ""  DCDC
 SG_ P2D_BUCK_FUN_RX_Byte7_43 : 48|8@1+ (1,0) [0|255] ""  DCDC
 SG_ P2D_BUCK_FUN_RX_Byte8_43 : 56|8@1+ (1,0) [0|255] ""  DCDC

BO_ 2148958060 P2D_BUCK_FUN_RX__44: 8 PC
 SG_ P2D_BUCK_FUN_RX_Byte1_44 : 0|8@1+ (1,0) [0|255] ""  DCDC
 SG_ P2D_BUCK_FUN_RX_Byte2_44 : 8|8@1+ (1,0) [0|255] ""  DCDC
 SG_ P2D_BUCK_FUN_RX_Byte3_44 : 16|8@1+ (1,0) [0|255] ""  DCDC
 SG_ P2D_BUCK_FUN_RX_Byte4_44 : 24|8@1+ (1,0) [0|255] ""  DCDC
 SG_ P2D_BUCK_FUN_RX_Byte5_44 : 32|8@1+ (1,0) [0|255] ""  DCDC
 SG_ P2D_BUCK_FUN_RX_Byte6_44 : 40|8@1+ (1,0) [0|255] ""  DCDC
 SG_ P2D_BUCK_FUN_RX_Byte7_44 : 48|8@1+ (1,0) [0|255] ""  DCDC
 SG_ P2D_BUCK_FUN_RX_Byte8_44 : 56|8@1+ (1,0) [0|255] ""  DCDC

BO_ 2148958061 P2D_BUCK_FUN_RX__45: 8 PC
 SG_ P2D_BUCK_FUN_RX_Byte1_45 : 0|8@1+ (1,0) [0|255] ""  DCDC
 SG_ P2D_BUCK_FUN_RX_Byte2_45 : 8|8@1+ (1,0) [0|255] ""  DCDC
 SG_ P2D_BUCK_FUN_RX_Byte3_45 : 16|8@1+ (1,0) [0|255] ""  DCDC
 SG_ P2D_BUCK_FUN_RX_Byte4_45 : 24|8@1+ (1,0) [0|255] ""  DCDC
 SG_ P2D_BUCK_FUN_RX_Byte5_45 : 32|8@1+ (1,0) [0|255] ""  DCDC
 SG_ P2D_BUCK_FUN_RX_Byte6_45 : 40|8@1+ (1,0) [0|255] ""  DCDC
 SG_ P2D_BUCK_FUN_RX_Byte7_45 : 48|8@1+ (1,0) [0|255] ""  DCDC
 SG_ P2D_BUCK_FUN_RX_Byte8_45 : 56|8@1+ (1,0) [0|255] ""  DCDC

BO_ 2148958062 P2D_BUCK_FUN_RX__46: 8 PC
 SG_ P2D_BUCK_FUN_RX_Byte1_46 : 0|8@1+ (1,0) [0|255] ""  DCDC
 SG_ P2D_BUCK_FUN_RX_Byte2_46 : 8|8@1+ (1,0) [0|255] ""  DCDC
 SG_ P2D_BUCK_FUN_RX_Byte3_46 : 16|8@1+ (1,0) [0|255] ""  DCDC
 SG_ P2D_BUCK_FUN_RX_Byte4_46 : 24|8@1+ (1,0) [0|255] ""  DCDC
 SG_ P2D_BUCK_FUN_RX_Byte5_46 : 32|8@1+ (1,0) [0|255] ""  DCDC
 SG_ P2D_BUCK_FUN_RX_Byte6_46 : 40|8@1+ (1,0) [0|255] ""  DCDC
 SG_ P2D_BUCK_FUN_RX_Byte7_46 : 48|8@1+ (1,0) [0|255] ""  DCDC
 SG_ P2D_BUCK_FUN_RX_Byte8_46 : 56|8@1+ (1,0) [0|255] ""  DCDC

BO_ 2148958063 P2D_BUCK_FUN_RX__47: 8 PC
 SG_ P2D_BUCK_FUN_RX_Byte1_47 : 0|8@1+ (1,0) [0|255] ""  DCDC
 SG_ P2D_BUCK_FUN_RX_Byte2_47 : 8|8@1+ (1,0) [0|255] ""  DCDC
 SG_ P2D_BUCK_FUN_RX_Byte3_47 : 16|8@1+ (1,0) [0|255] ""  DCDC
 SG_ P2D_BUCK_FUN_RX_Byte4_47 : 24|8@1+ (1,0) [0|255] ""  DCDC
 SG_ P2D_BUCK_FUN_RX_Byte5_47 : 32|8@1+ (1,0) [0|255] ""  DCDC
 SG_ P2D_BUCK_FUN_RX_Byte6_47 : 40|8@1+ (1,0) [0|255] ""  DCDC
 SG_ P2D_BUCK_FUN_RX_Byte7_47 : 48|8@1+ (1,0) [0|255] ""  DCDC
 SG_ P2D_BUCK_FUN_RX_Byte8_47 : 56|8@1+ (1,0) [0|255] ""  DCDC

BO_ 2148958064 P2D_BUCK_FUN_RX__48: 8 PC
 SG_ P2D_BUCK_FUN_RX_Byte1_48 : 0|8@1+ (1,0) [0|255] ""  DCDC
 SG_ P2D_BUCK_FUN_RX_Byte2_48 : 8|8@1+ (1,0) [0|255] ""  DCDC
 SG_ P2D_BUCK_FUN_RX_Byte3_48 : 16|8@1+ (1,0) [0|255] ""  DCDC
 SG_ P2D_BUCK_FUN_RX_Byte4_48 : 24|8@1+ (1,0) [0|255] ""  DCDC
 SG_ P2D_BUCK_FUN_RX_Byte5_48 : 32|8@1+ (1,0) [0|255] ""  DCDC
 SG_ P2D_BUCK_FUN_RX_Byte6_48 : 40|8@1+ (1,0) [0|255] ""  DCDC
 SG_ P2D_BUCK_FUN_RX_Byte7_48 : 48|8@1+ (1,0) [0|255] ""  DCDC
 SG_ P2D_BUCK_FUN_RX_Byte8_48 : 56|8@1+ (1,0) [0|255] ""  DCDC

BO_ 2148958065 P2D_BUCK_FUN_RX__49: 8 PC
 SG_ P2D_BUCK_FUN_RX_Byte1_49 : 0|8@1+ (1,0) [0|255] ""  DCDC
 SG_ P2D_BUCK_FUN_RX_Byte2_49 : 8|8@1+ (1,0) [0|255] ""  DCDC
 SG_ P2D_BUCK_FUN_RX_Byte3_49 : 16|8@1+ (1,0) [0|255] ""  DCDC
 SG_ P2D_BUCK_FUN_RX_Byte4_49 : 24|8@1+ (1,0) [0|255] ""  DCDC
 SG_ P2D_BUCK_FUN_RX_Byte5_49 : 32|8@1+ (1,0) [0|255] ""  DCDC
 SG_ P2D_BUCK_FUN_RX_Byte6_49 : 40|8@1+ (1,0) [0|255] ""  DCDC
 SG_ P2D_BUCK_FUN_RX_Byte7_49 : 48|8@1+ (1,0) [0|255] ""  DCDC
 SG_ P2D_BUCK_FUN_RX_Byte8_49 : 56|8@1+ (1,0) [0|255] ""  DCDC

BO_ 2148958066 P2D_BUCK_FUN_RX__50: 8 PC
 SG_ P2D_BUCK_FUN_RX_Byte1_50 : 0|8@1+ (1,0) [0|255] ""  DCDC
 SG_ P2D_BUCK_FUN_RX_Byte2_50 : 8|8@1+ (1,0) [0|255] ""  DCDC
 SG_ P2D_BUCK_FUN_RX_Byte3_50 : 16|8@1+ (1,0) [0|255] ""  DCDC
 SG_ P2D_BUCK_FUN_RX_Byte4_50 : 24|8@1+ (1,0) [0|255] ""  DCDC
 SG_ P2D_BUCK_FUN_RX_Byte5_50 : 32|8@1+ (1,0) [0|255] ""  DCDC
 SG_ P2D_BUCK_FUN_RX_Byte6_50 : 40|8@1+ (1,0) [0|255] ""  DCDC
 SG_ P2D_BUCK_FUN_RX_Byte7_50 : 48|8@1+ (1,0) [0|255] ""  DCDC
 SG_ P2D_BUCK_FUN_RX_Byte8_50 : 56|8@1+ (1,0) [0|255] ""  DCDC

BO_ 2148958067 P2D_BUCK_FUN_RX__51: 8 PC
 SG_ P2D_BUCK_FUN_RX_Byte1_51 : 0|8@1+ (1,0) [0|255] ""  DCDC
 SG_ P2D_BUCK_FUN_RX_Byte2_51 : 8|8@1+ (1,0) [0|255] ""  DCDC
 SG_ P2D_BUCK_FUN_RX_Byte3_51 : 16|8@1+ (1,0) [0|255] ""  DCDC
 SG_ P2D_BUCK_FUN_RX_Byte4_51 : 24|8@1+ (1,0) [0|255] ""  DCDC
 SG_ P2D_BUCK_FUN_RX_Byte5_51 : 32|8@1+ (1,0) [0|255] ""  DCDC
 SG_ P2D_BUCK_FUN_RX_Byte6_51 : 40|8@1+ (1,0) [0|255] ""  DCDC
 SG_ P2D_BUCK_FUN_RX_Byte7_51 : 48|8@1+ (1,0) [0|255] ""  DCDC
 SG_ P2D_BUCK_FUN_RX_Byte8_51 : 56|8@1+ (1,0) [0|255] ""  DCDC

BO_ 2148958068 P2D_BUCK_FUN_RX__52: 8 PC
 SG_ P2D_BUCK_FUN_RX_Byte1_52 : 0|8@1+ (1,0) [0|255] ""  DCDC
 SG_ P2D_BUCK_FUN_RX_Byte2_52 : 8|8@1+ (1,0) [0|255] ""  DCDC
 SG_ P2D_BUCK_FUN_RX_Byte3_52 : 16|8@1+ (1,0) [0|255] ""  DCDC
 SG_ P2D_BUCK_FUN_RX_Byte4_52 : 24|8@1+ (1,0) [0|255] ""  DCDC
 SG_ P2D_BUCK_FUN_RX_Byte5_52 : 32|8@1+ (1,0) [0|255] ""  DCDC
 SG_ P2D_BUCK_FUN_RX_Byte6_52 : 40|8@1+ (1,0) [0|255] ""  DCDC
 SG_ P2D_BUCK_FUN_RX_Byte7_52 : 48|8@1+ (1,0) [0|255] ""  DCDC
 SG_ P2D_BUCK_FUN_RX_Byte8_52 : 56|8@1+ (1,0) [0|255] ""  DCDC

BO_ 2148958069 P2D_BUCK_FUN_RX__53: 8 PC
 SG_ P2D_BUCK_FUN_RX_Byte1_53 : 0|8@1+ (1,0) [0|255] ""  DCDC
 SG_ P2D_BUCK_FUN_RX_Byte2_53 : 8|8@1+ (1,0) [0|255] ""  DCDC
 SG_ P2D_BUCK_FUN_RX_Byte3_53 : 16|8@1+ (1,0) [0|255] ""  DCDC
 SG_ P2D_BUCK_FUN_RX_Byte4_53 : 24|8@1+ (1,0) [0|255] ""  DCDC
 SG_ P2D_BUCK_FUN_RX_Byte5_53 : 32|8@1+ (1,0) [0|255] ""  DCDC
 SG_ P2D_BUCK_FUN_RX_Byte6_53 : 40|8@1+ (1,0) [0|255] ""  DCDC
 SG_ P2D_BUCK_FUN_RX_Byte7_53 : 48|8@1+ (1,0) [0|255] ""  DCDC
 SG_ P2D_BUCK_FUN_RX_Byte8_53 : 56|8@1+ (1,0) [0|255] ""  DCDC

BO_ 2148958070 P2D_BUCK_FUN_RX__54: 8 PC
 SG_ P2D_BUCK_FUN_RX_Byte1_54 : 0|8@1+ (1,0) [0|255] ""  DCDC
 SG_ P2D_BUCK_FUN_RX_Byte2_54 : 8|8@1+ (1,0) [0|255] ""  DCDC
 SG_ P2D_BUCK_FUN_RX_Byte3_54 : 16|8@1+ (1,0) [0|255] ""  DCDC
 SG_ P2D_BUCK_FUN_RX_Byte4_54 : 24|8@1+ (1,0) [0|255] ""  DCDC
 SG_ P2D_BUCK_FUN_RX_Byte5_54 : 32|8@1+ (1,0) [0|255] ""  DCDC
 SG_ P2D_BUCK_FUN_RX_Byte6_54 : 40|8@1+ (1,0) [0|255] ""  DCDC
 SG_ P2D_BUCK_FUN_RX_Byte7_54 : 48|8@1+ (1,0) [0|255] ""  DCDC
 SG_ P2D_BUCK_FUN_RX_Byte8_54 : 56|8@1+ (1,0) [0|255] ""  DCDC

BO_ 2148958071 P2D_BUCK_FUN_RX__55: 8 PC
 SG_ P2D_BUCK_FUN_RX_Byte1_55 : 0|8@1+ (1,0) [0|255] ""  DCDC
 SG_ P2D_BUCK_FUN_RX_Byte2_55 : 8|8@1+ (1,0) [0|255] ""  DCDC
 SG_ P2D_BUCK_FUN_RX_Byte3_55 : 16|8@1+ (1,0) [0|255] ""  DCDC
 SG_ P2D_BUCK_FUN_RX_Byte4_55 : 24|8@1+ (1,0) [0|255] ""  DCDC
 SG_ P2D_BUCK_FUN_RX_Byte5_55 : 32|8@1+ (1,0) [0|255] ""  DCDC
 SG_ P2D_BUCK_FUN_RX_Byte6_55 : 40|8@1+ (1,0) [0|255] ""  DCDC
 SG_ P2D_BUCK_FUN_RX_Byte7_55 : 48|8@1+ (1,0) [0|255] ""  DCDC
 SG_ P2D_BUCK_FUN_RX_Byte8_55 : 56|8@1+ (1,0) [0|255] ""  DCDC

BO_ 2148958072 P2D_BUCK_FUN_RX__56: 8 PC
 SG_ P2D_BUCK_FUN_RX_Byte1_56 : 0|8@1+ (1,0) [0|255] ""  DCDC
 SG_ P2D_BUCK_FUN_RX_Byte2_56 : 8|8@1+ (1,0) [0|255] ""  DCDC
 SG_ P2D_BUCK_FUN_RX_Byte3_56 : 16|8@1+ (1,0) [0|255] ""  DCDC
 SG_ P2D_BUCK_FUN_RX_Byte4_56 : 24|8@1+ (1,0) [0|255] ""  DCDC
 SG_ P2D_BUCK_FUN_RX_Byte5_56 : 32|8@1+ (1,0) [0|255] ""  DCDC
 SG_ P2D_BUCK_FUN_RX_Byte6_56 : 40|8@1+ (1,0) [0|255] ""  DCDC
 SG_ P2D_BUCK_FUN_RX_Byte7_56 : 48|8@1+ (1,0) [0|255] ""  DCDC
 SG_ P2D_BUCK_FUN_RX_Byte8_56 : 56|8@1+ (1,0) [0|255] ""  DCDC

BO_ 2148958073 P2D_BUCK_FUN_RX__57: 8 PC
 SG_ P2D_BUCK_FUN_RX_Byte1_57 : 0|8@1+ (1,0) [0|255] ""  DCDC
 SG_ P2D_BUCK_FUN_RX_Byte2_57 : 8|8@1+ (1,0) [0|255] ""  DCDC
 SG_ P2D_BUCK_FUN_RX_Byte3_57 : 16|8@1+ (1,0) [0|255] ""  DCDC
 SG_ P2D_BUCK_FUN_RX_Byte4_57 : 24|8@1+ (1,0) [0|255] ""  DCDC
 SG_ P2D_BUCK_FUN_RX_Byte5_57 : 32|8@1+ (1,0) [0|255] ""  DCDC
 SG_ P2D_BUCK_FUN_RX_Byte6_57 : 40|8@1+ (1,0) [0|255] ""  DCDC
 SG_ P2D_BUCK_FUN_RX_Byte7_57 : 48|8@1+ (1,0) [0|255] ""  DCDC
 SG_ P2D_BUCK_FUN_RX_Byte8_57 : 56|8@1+ (1,0) [0|255] ""  DCDC

BO_ 2148958074 P2D_BUCK_FUN_RX__58: 8 PC
 SG_ P2D_BUCK_FUN_RX_Byte1_58 : 0|8@1+ (1,0) [0|255] ""  DCDC
 SG_ P2D_BUCK_FUN_RX_Byte2_58 : 8|8@1+ (1,0) [0|255] ""  DCDC
 SG_ P2D_BUCK_FUN_RX_Byte3_58 : 16|8@1+ (1,0) [0|255] ""  DCDC
 SG_ P2D_BUCK_FUN_RX_Byte4_58 : 24|8@1+ (1,0) [0|255] ""  DCDC
 SG_ P2D_BUCK_FUN_RX_Byte5_58 : 32|8@1+ (1,0) [0|255] ""  DCDC
 SG_ P2D_BUCK_FUN_RX_Byte6_58 : 40|8@1+ (1,0) [0|255] ""  DCDC
 SG_ P2D_BUCK_FUN_RX_Byte7_58 : 48|8@1+ (1,0) [0|255] ""  DCDC
 SG_ P2D_BUCK_FUN_RX_Byte8_58 : 56|8@1+ (1,0) [0|255] ""  DCDC

BO_ 2148958075 P2D_BUCK_FUN_RX__59: 8 PC
 SG_ P2D_BUCK_FUN_RX_Byte1_59 : 0|8@1+ (1,0) [0|255] ""  DCDC
 SG_ P2D_BUCK_FUN_RX_Byte2_59 : 8|8@1+ (1,0) [0|255] ""  DCDC
 SG_ P2D_BUCK_FUN_RX_Byte3_59 : 16|8@1+ (1,0) [0|255] ""  DCDC
 SG_ P2D_BUCK_FUN_RX_Byte4_59 : 24|8@1+ (1,0) [0|255] ""  DCDC
 SG_ P2D_BUCK_FUN_RX_Byte5_59 : 32|8@1+ (1,0) [0|255] ""  DCDC
 SG_ P2D_BUCK_FUN_RX_Byte6_59 : 40|8@1+ (1,0) [0|255] ""  DCDC
 SG_ P2D_BUCK_FUN_RX_Byte7_59 : 48|8@1+ (1,0) [0|255] ""  DCDC
 SG_ P2D_BUCK_FUN_RX_Byte8_59 : 56|8@1+ (1,0) [0|255] ""  DCDC

BO_ 2148958076 P2D_BUCK_FUN_RX__60: 8 PC
 SG_ P2D_BUCK_FUN_RX_Byte1_60 : 0|8@1+ (1,0) [0|255] ""  DCDC
 SG_ P2D_BUCK_FUN_RX_Byte2_60 : 8|8@1+ (1,0) [0|255] ""  DCDC
 SG_ P2D_BUCK_FUN_RX_Byte3_60 : 16|8@1+ (1,0) [0|255] ""  DCDC
 SG_ P2D_BUCK_FUN_RX_Byte4_60 : 24|8@1+ (1,0) [0|255] ""  DCDC
 SG_ P2D_BUCK_FUN_RX_Byte5_60 : 32|8@1+ (1,0) [0|255] ""  DCDC
 SG_ P2D_BUCK_FUN_RX_Byte6_60 : 40|8@1+ (1,0) [0|255] ""  DCDC
 SG_ P2D_BUCK_FUN_RX_Byte7_60 : 48|8@1+ (1,0) [0|255] ""  DCDC
 SG_ P2D_BUCK_FUN_RX_Byte8_60 : 56|8@1+ (1,0) [0|255] ""  DCDC

BO_ 2148958077 P2D_BUCK_FUN_RX__61: 8 PC
 SG_ P2D_BUCK_FUN_RX_Byte1_61 : 0|8@1+ (1,0) [0|255] ""  DCDC
 SG_ P2D_BUCK_FUN_RX_Byte2_61 : 8|8@1+ (1,0) [0|255] ""  DCDC
 SG_ P2D_BUCK_FUN_RX_Byte3_61 : 16|8@1+ (1,0) [0|255] ""  DCDC
 SG_ P2D_BUCK_FUN_RX_Byte4_61 : 24|8@1+ (1,0) [0|255] ""  DCDC
 SG_ P2D_BUCK_FUN_RX_Byte5_61 : 32|8@1+ (1,0) [0|255] ""  DCDC
 SG_ P2D_BUCK_FUN_RX_Byte6_61 : 40|8@1+ (1,0) [0|255] ""  DCDC
 SG_ P2D_BUCK_FUN_RX_Byte7_61 : 48|8@1+ (1,0) [0|255] ""  DCDC
 SG_ P2D_BUCK_FUN_RX_Byte8_61 : 56|8@1+ (1,0) [0|255] ""  DCDC

BO_ 2148958078 P2D_BUCK_FUN_RX__62: 8 PC
 SG_ P2D_BUCK_FUN_RX_Byte1_62 : 0|8@1+ (1,0) [0|255] ""  DCDC
 SG_ P2D_BUCK_FUN_RX_Byte2_62 : 8|8@1+ (1,0) [0|255] ""  DCDC
 SG_ P2D_BUCK_FUN_RX_Byte3_62 : 16|8@1+ (1,0) [0|255] ""  DCDC
 SG_ P2D_BUCK_FUN_RX_Byte4_62 : 24|8@1+ (1,0) [0|255] ""  DCDC
 SG_ P2D_BUCK_FUN_RX_Byte5_62 : 32|8@1+ (1,0) [0|255] ""  DCDC
 SG_ P2D_BUCK_FUN_RX_Byte6_62 : 40|8@1+ (1,0) [0|255] ""  DCDC
 SG_ P2D_BUCK_FUN_RX_Byte7_62 : 48|8@1+ (1,0) [0|255] ""  DCDC
 SG_ P2D_BUCK_FUN_RX_Byte8_62 : 56|8@1+ (1,0) [0|255] ""  DCDC

BO_ 2148958079 P2D_BUCK_FUN_RX__63: 8 PC
 SG_ P2D_BUCK_FUN_RX_Byte1_63 : 0|8@1+ (1,0) [0|255] ""  DCDC
 SG_ P2D_BUCK_FUN_RX_Byte2_63 : 8|8@1+ (1,0) [0|255] ""  DCDC
 SG_ P2D_BUCK_FUN_RX_Byte3_63 : 16|8@1+ (1,0) [0|255] ""  DCDC
 SG_ P2D_BUCK_FUN_RX_Byte4_63 : 24|8@1+ (1,0) [0|255] ""  DCDC
 SG_ P2D_BUCK_FUN_RX_Byte5_63 : 32|8@1+ (1,0) [0|255] ""  DCDC
 SG_ P2D_BUCK_FUN_RX_Byte6_63 : 40|8@1+ (1,0) [0|255] ""  DCDC
 SG_ P2D_BUCK_FUN_RX_Byte7_63 : 48|8@1+ (1,0) [0|255] ""  DCDC
 SG_ P2D_BUCK_FUN_RX_Byte8_63 : 56|8@1+ (1,0) [0|255] ""  DCDC

BO_ 2149023553 P2D_BUCK_PHY_RX__01: 8 PC
 SG_ P2D_BUCK_PHY_RX_Byte1_01 : 0|8@1+ (1,0) [0|255] ""  DCDC
 SG_ P2D_BUCK_PHY_RX_Byte2_01 : 8|8@1+ (1,0) [0|255] ""  DCDC
 SG_ P2D_BUCK_PHY_RX_Byte3_01 : 16|8@1+ (1,0) [0|255] ""  DCDC
 SG_ P2D_BUCK_PHY_RX_Byte4_01 : 24|8@1+ (1,0) [0|255] ""  DCDC
 SG_ P2D_BUCK_PHY_RX_Byte5_01 : 32|8@1+ (1,0) [0|255] ""  DCDC
 SG_ P2D_BUCK_PHY_RX_Byte6_01 : 40|8@1+ (1,0) [0|255] ""  DCDC
 SG_ P2D_BUCK_PHY_RX_Byte7_01 : 48|8@1+ (1,0) [0|255] ""  DCDC
 SG_ P2D_BUCK_PHY_RX_Byte8_01 : 56|8@1+ (1,0) [0|255] ""  DCDC

BO_ 2149023554 P2D_BUCK_PHY_RX__02: 8 PC
 SG_ P2D_BUCK_PHY_RX_Byte1_02 : 0|8@1+ (1,0) [0|255] ""  DCDC
 SG_ P2D_BUCK_PHY_RX_Byte2_02 : 8|8@1+ (1,0) [0|255] ""  DCDC
 SG_ P2D_BUCK_PHY_RX_Byte3_02 : 16|8@1+ (1,0) [0|255] ""  DCDC
 SG_ P2D_BUCK_PHY_RX_Byte4_02 : 24|8@1+ (1,0) [0|255] ""  DCDC
 SG_ P2D_BUCK_PHY_RX_Byte5_02 : 32|8@1+ (1,0) [0|255] ""  DCDC
 SG_ P2D_BUCK_PHY_RX_Byte6_02 : 40|8@1+ (1,0) [0|255] ""  DCDC
 SG_ P2D_BUCK_PHY_RX_Byte7_02 : 48|8@1+ (1,0) [0|255] ""  DCDC
 SG_ P2D_BUCK_PHY_RX_Byte8_02 : 56|8@1+ (1,0) [0|255] ""  DCDC

BO_ 2149023555 P2D_BUCK_PHY_RX__03: 8 PC
 SG_ P2D_BUCK_PHY_RX_Byte1_03 : 0|8@1+ (1,0) [0|255] ""  DCDC
 SG_ P2D_BUCK_PHY_RX_Byte2_03 : 8|8@1+ (1,0) [0|255] ""  DCDC
 SG_ P2D_BUCK_PHY_RX_Byte3_03 : 16|8@1+ (1,0) [0|255] ""  DCDC
 SG_ P2D_BUCK_PHY_RX_Byte4_03 : 24|8@1+ (1,0) [0|255] ""  DCDC
 SG_ P2D_BUCK_PHY_RX_Byte5_03 : 32|8@1+ (1,0) [0|255] ""  DCDC
 SG_ P2D_BUCK_PHY_RX_Byte6_03 : 40|8@1+ (1,0) [0|255] ""  DCDC
 SG_ P2D_BUCK_PHY_RX_Byte7_03 : 48|8@1+ (1,0) [0|255] ""  DCDC
 SG_ P2D_BUCK_PHY_RX_Byte8_03 : 56|8@1+ (1,0) [0|255] ""  DCDC

BO_ 2149023556 P2D_BUCK_PHY_RX__04: 8 PC
 SG_ P2D_BUCK_PHY_RX_Byte1_04 : 0|8@1+ (1,0) [0|255] ""  DCDC
 SG_ P2D_BUCK_PHY_RX_Byte2_04 : 8|8@1+ (1,0) [0|255] ""  DCDC
 SG_ P2D_BUCK_PHY_RX_Byte3_04 : 16|8@1+ (1,0) [0|255] ""  DCDC
 SG_ P2D_BUCK_PHY_RX_Byte4_04 : 24|8@1+ (1,0) [0|255] ""  DCDC
 SG_ P2D_BUCK_PHY_RX_Byte5_04 : 32|8@1+ (1,0) [0|255] ""  DCDC
 SG_ P2D_BUCK_PHY_RX_Byte6_04 : 40|8@1+ (1,0) [0|255] ""  DCDC
 SG_ P2D_BUCK_PHY_RX_Byte7_04 : 48|8@1+ (1,0) [0|255] ""  DCDC
 SG_ P2D_BUCK_PHY_RX_Byte8_04 : 56|8@1+ (1,0) [0|255] ""  DCDC

BO_ 2149023557 P2D_BUCK_PHY_RX__05: 8 PC
 SG_ P2D_BUCK_PHY_RX_Byte1_05 : 0|8@1+ (1,0) [0|255] ""  DCDC
 SG_ P2D_BUCK_PHY_RX_Byte2_05 : 8|8@1+ (1,0) [0|255] ""  DCDC
 SG_ P2D_BUCK_PHY_RX_Byte3_05 : 16|8@1+ (1,0) [0|255] ""  DCDC
 SG_ P2D_BUCK_PHY_RX_Byte4_05 : 24|8@1+ (1,0) [0|255] ""  DCDC
 SG_ P2D_BUCK_PHY_RX_Byte5_05 : 32|8@1+ (1,0) [0|255] ""  DCDC
 SG_ P2D_BUCK_PHY_RX_Byte6_05 : 40|8@1+ (1,0) [0|255] ""  DCDC
 SG_ P2D_BUCK_PHY_RX_Byte7_05 : 48|8@1+ (1,0) [0|255] ""  DCDC
 SG_ P2D_BUCK_PHY_RX_Byte8_05 : 56|8@1+ (1,0) [0|255] ""  DCDC

BO_ 2149023558 P2D_BUCK_PHY_RX__06: 8 PC
 SG_ P2D_BUCK_PHY_RX_Byte1_06 : 0|8@1+ (1,0) [0|255] ""  DCDC
 SG_ P2D_BUCK_PHY_RX_Byte2_06 : 8|8@1+ (1,0) [0|255] ""  DCDC
 SG_ P2D_BUCK_PHY_RX_Byte3_06 : 16|8@1+ (1,0) [0|255] ""  DCDC
 SG_ P2D_BUCK_PHY_RX_Byte4_06 : 24|8@1+ (1,0) [0|255] ""  DCDC
 SG_ P2D_BUCK_PHY_RX_Byte5_06 : 32|8@1+ (1,0) [0|255] ""  DCDC
 SG_ P2D_BUCK_PHY_RX_Byte6_06 : 40|8@1+ (1,0) [0|255] ""  DCDC
 SG_ P2D_BUCK_PHY_RX_Byte7_06 : 48|8@1+ (1,0) [0|255] ""  DCDC
 SG_ P2D_BUCK_PHY_RX_Byte8_06 : 56|8@1+ (1,0) [0|255] ""  DCDC

BO_ 2149023559 P2D_BUCK_PHY_RX__07: 8 PC
 SG_ P2D_BUCK_PHY_RX_Byte1_07 : 0|8@1+ (1,0) [0|255] ""  DCDC
 SG_ P2D_BUCK_PHY_RX_Byte2_07 : 8|8@1+ (1,0) [0|255] ""  DCDC
 SG_ P2D_BUCK_PHY_RX_Byte3_07 : 16|8@1+ (1,0) [0|255] ""  DCDC
 SG_ P2D_BUCK_PHY_RX_Byte4_07 : 24|8@1+ (1,0) [0|255] ""  DCDC
 SG_ P2D_BUCK_PHY_RX_Byte5_07 : 32|8@1+ (1,0) [0|255] ""  DCDC
 SG_ P2D_BUCK_PHY_RX_Byte6_07 : 40|8@1+ (1,0) [0|255] ""  DCDC
 SG_ P2D_BUCK_PHY_RX_Byte7_07 : 48|8@1+ (1,0) [0|255] ""  DCDC
 SG_ P2D_BUCK_PHY_RX_Byte8_07 : 56|8@1+ (1,0) [0|255] ""  DCDC

BO_ 2149023560 P2D_BUCK_PHY_RX__08: 8 PC
 SG_ P2D_BUCK_PHY_RX_Byte1_08 : 0|8@1+ (1,0) [0|255] ""  DCDC
 SG_ P2D_BUCK_PHY_RX_Byte2_08 : 8|8@1+ (1,0) [0|255] ""  DCDC
 SG_ P2D_BUCK_PHY_RX_Byte3_08 : 16|8@1+ (1,0) [0|255] ""  DCDC
 SG_ P2D_BUCK_PHY_RX_Byte4_08 : 24|8@1+ (1,0) [0|255] ""  DCDC
 SG_ P2D_BUCK_PHY_RX_Byte5_08 : 32|8@1+ (1,0) [0|255] ""  DCDC
 SG_ P2D_BUCK_PHY_RX_Byte6_08 : 40|8@1+ (1,0) [0|255] ""  DCDC
 SG_ P2D_BUCK_PHY_RX_Byte7_08 : 48|8@1+ (1,0) [0|255] ""  DCDC
 SG_ P2D_BUCK_PHY_RX_Byte8_08 : 56|8@1+ (1,0) [0|255] ""  DCDC

BO_ 2149023561 P2D_BUCK_PHY_RX__09: 8 PC
 SG_ P2D_BUCK_PHY_RX_Byte1_09 : 0|8@1+ (1,0) [0|255] ""  DCDC
 SG_ P2D_BUCK_PHY_RX_Byte2_09 : 8|8@1+ (1,0) [0|255] ""  DCDC
 SG_ P2D_BUCK_PHY_RX_Byte3_09 : 16|8@1+ (1,0) [0|255] ""  DCDC
 SG_ P2D_BUCK_PHY_RX_Byte4_09 : 24|8@1+ (1,0) [0|255] ""  DCDC
 SG_ P2D_BUCK_PHY_RX_Byte5_09 : 32|8@1+ (1,0) [0|255] ""  DCDC
 SG_ P2D_BUCK_PHY_RX_Byte6_09 : 40|8@1+ (1,0) [0|255] ""  DCDC
 SG_ P2D_BUCK_PHY_RX_Byte7_09 : 48|8@1+ (1,0) [0|255] ""  DCDC
 SG_ P2D_BUCK_PHY_RX_Byte8_09 : 56|8@1+ (1,0) [0|255] ""  DCDC

BO_ 2149023562 P2D_BUCK_PHY_RX__10: 8 PC
 SG_ P2D_BUCK_PHY_RX_Byte1_10 : 0|8@1+ (1,0) [0|255] ""  DCDC
 SG_ P2D_BUCK_PHY_RX_Byte2_10 : 8|8@1+ (1,0) [0|255] ""  DCDC
 SG_ P2D_BUCK_PHY_RX_Byte3_10 : 16|8@1+ (1,0) [0|255] ""  DCDC
 SG_ P2D_BUCK_PHY_RX_Byte4_10 : 24|8@1+ (1,0) [0|255] ""  DCDC
 SG_ P2D_BUCK_PHY_RX_Byte5_10 : 32|8@1+ (1,0) [0|255] ""  DCDC
 SG_ P2D_BUCK_PHY_RX_Byte6_10 : 40|8@1+ (1,0) [0|255] ""  DCDC
 SG_ P2D_BUCK_PHY_RX_Byte7_10 : 48|8@1+ (1,0) [0|255] ""  DCDC
 SG_ P2D_BUCK_PHY_RX_Byte8_10 : 56|8@1+ (1,0) [0|255] ""  DCDC

BO_ 2149023563 P2D_BUCK_PHY_RX__11: 8 PC
 SG_ P2D_BUCK_PHY_RX_Byte1_11 : 0|8@1+ (1,0) [0|255] ""  DCDC
 SG_ P2D_BUCK_PHY_RX_Byte2_11 : 8|8@1+ (1,0) [0|255] ""  DCDC
 SG_ P2D_BUCK_PHY_RX_Byte3_11 : 16|8@1+ (1,0) [0|255] ""  DCDC
 SG_ P2D_BUCK_PHY_RX_Byte4_11 : 24|8@1+ (1,0) [0|255] ""  DCDC
 SG_ P2D_BUCK_PHY_RX_Byte5_11 : 32|8@1+ (1,0) [0|255] ""  DCDC
 SG_ P2D_BUCK_PHY_RX_Byte6_11 : 40|8@1+ (1,0) [0|255] ""  DCDC
 SG_ P2D_BUCK_PHY_RX_Byte7_11 : 48|8@1+ (1,0) [0|255] ""  DCDC
 SG_ P2D_BUCK_PHY_RX_Byte8_11 : 56|8@1+ (1,0) [0|255] ""  DCDC

BO_ 2149023564 P2D_BUCK_PHY_RX__12: 8 PC
 SG_ P2D_BUCK_PHY_RX_Byte1_12 : 0|8@1+ (1,0) [0|255] ""  DCDC
 SG_ P2D_BUCK_PHY_RX_Byte2_12 : 8|8@1+ (1,0) [0|255] ""  DCDC
 SG_ P2D_BUCK_PHY_RX_Byte3_12 : 16|8@1+ (1,0) [0|255] ""  DCDC
 SG_ P2D_BUCK_PHY_RX_Byte4_12 : 24|8@1+ (1,0) [0|255] ""  DCDC
 SG_ P2D_BUCK_PHY_RX_Byte5_12 : 32|8@1+ (1,0) [0|255] ""  DCDC
 SG_ P2D_BUCK_PHY_RX_Byte6_12 : 40|8@1+ (1,0) [0|255] ""  DCDC
 SG_ P2D_BUCK_PHY_RX_Byte7_12 : 48|8@1+ (1,0) [0|255] ""  DCDC
 SG_ P2D_BUCK_PHY_RX_Byte8_12 : 56|8@1+ (1,0) [0|255] ""  DCDC

BO_ 2149023565 P2D_BUCK_PHY_RX__13: 8 PC
 SG_ P2D_BUCK_PHY_RX_Byte1_13 : 0|8@1+ (1,0) [0|255] ""  DCDC
 SG_ P2D_BUCK_PHY_RX_Byte2_13 : 8|8@1+ (1,0) [0|255] ""  DCDC
 SG_ P2D_BUCK_PHY_RX_Byte3_13 : 16|8@1+ (1,0) [0|255] ""  DCDC
 SG_ P2D_BUCK_PHY_RX_Byte4_13 : 24|8@1+ (1,0) [0|255] ""  DCDC
 SG_ P2D_BUCK_PHY_RX_Byte5_13 : 32|8@1+ (1,0) [0|255] ""  DCDC
 SG_ P2D_BUCK_PHY_RX_Byte6_13 : 40|8@1+ (1,0) [0|255] ""  DCDC
 SG_ P2D_BUCK_PHY_RX_Byte7_13 : 48|8@1+ (1,0) [0|255] ""  DCDC
 SG_ P2D_BUCK_PHY_RX_Byte8_13 : 56|8@1+ (1,0) [0|255] ""  DCDC

BO_ 2149023566 P2D_BUCK_PHY_RX__14: 8 PC
 SG_ P2D_BUCK_PHY_RX_Byte1_14 : 0|8@1+ (1,0) [0|255] ""  DCDC
 SG_ P2D_BUCK_PHY_RX_Byte2_14 : 8|8@1+ (1,0) [0|255] ""  DCDC
 SG_ P2D_BUCK_PHY_RX_Byte3_14 : 16|8@1+ (1,0) [0|255] ""  DCDC
 SG_ P2D_BUCK_PHY_RX_Byte4_14 : 24|8@1+ (1,0) [0|255] ""  DCDC
 SG_ P2D_BUCK_PHY_RX_Byte5_14 : 32|8@1+ (1,0) [0|255] ""  DCDC
 SG_ P2D_BUCK_PHY_RX_Byte6_14 : 40|8@1+ (1,0) [0|255] ""  DCDC
 SG_ P2D_BUCK_PHY_RX_Byte7_14 : 48|8@1+ (1,0) [0|255] ""  DCDC
 SG_ P2D_BUCK_PHY_RX_Byte8_14 : 56|8@1+ (1,0) [0|255] ""  DCDC

BO_ 2149023567 P2D_BUCK_PHY_RX__15: 8 PC
 SG_ P2D_BUCK_PHY_RX_Byte1_15 : 0|8@1+ (1,0) [0|255] ""  DCDC
 SG_ P2D_BUCK_PHY_RX_Byte2_15 : 8|8@1+ (1,0) [0|255] ""  DCDC
 SG_ P2D_BUCK_PHY_RX_Byte3_15 : 16|8@1+ (1,0) [0|255] ""  DCDC
 SG_ P2D_BUCK_PHY_RX_Byte4_15 : 24|8@1+ (1,0) [0|255] ""  DCDC
 SG_ P2D_BUCK_PHY_RX_Byte5_15 : 32|8@1+ (1,0) [0|255] ""  DCDC
 SG_ P2D_BUCK_PHY_RX_Byte6_15 : 40|8@1+ (1,0) [0|255] ""  DCDC
 SG_ P2D_BUCK_PHY_RX_Byte7_15 : 48|8@1+ (1,0) [0|255] ""  DCDC
 SG_ P2D_BUCK_PHY_RX_Byte8_15 : 56|8@1+ (1,0) [0|255] ""  DCDC

BO_ 2149023568 P2D_BUCK_PHY_RX__16: 8 PC
 SG_ P2D_BUCK_PHY_RX_Byte1_16 : 0|8@1+ (1,0) [0|255] ""  DCDC
 SG_ P2D_BUCK_PHY_RX_Byte2_16 : 8|8@1+ (1,0) [0|255] ""  DCDC
 SG_ P2D_BUCK_PHY_RX_Byte3_16 : 16|8@1+ (1,0) [0|255] ""  DCDC
 SG_ P2D_BUCK_PHY_RX_Byte4_16 : 24|8@1+ (1,0) [0|255] ""  DCDC
 SG_ P2D_BUCK_PHY_RX_Byte5_16 : 32|8@1+ (1,0) [0|255] ""  DCDC
 SG_ P2D_BUCK_PHY_RX_Byte6_16 : 40|8@1+ (1,0) [0|255] ""  DCDC
 SG_ P2D_BUCK_PHY_RX_Byte7_16 : 48|8@1+ (1,0) [0|255] ""  DCDC
 SG_ P2D_BUCK_PHY_RX_Byte8_16 : 56|8@1+ (1,0) [0|255] ""  DCDC

BO_ 2149023569 P2D_BUCK_PHY_RX__17: 8 PC
 SG_ P2D_BUCK_PHY_RX_Byte1_17 : 0|8@1+ (1,0) [0|255] ""  DCDC
 SG_ P2D_BUCK_PHY_RX_Byte2_17 : 8|8@1+ (1,0) [0|255] ""  DCDC
 SG_ P2D_BUCK_PHY_RX_Byte3_17 : 16|8@1+ (1,0) [0|255] ""  DCDC
 SG_ P2D_BUCK_PHY_RX_Byte4_17 : 24|8@1+ (1,0) [0|255] ""  DCDC
 SG_ P2D_BUCK_PHY_RX_Byte5_17 : 32|8@1+ (1,0) [0|255] ""  DCDC
 SG_ P2D_BUCK_PHY_RX_Byte6_17 : 40|8@1+ (1,0) [0|255] ""  DCDC
 SG_ P2D_BUCK_PHY_RX_Byte7_17 : 48|8@1+ (1,0) [0|255] ""  DCDC
 SG_ P2D_BUCK_PHY_RX_Byte8_17 : 56|8@1+ (1,0) [0|255] ""  DCDC

BO_ 2149023570 P2D_BUCK_PHY_RX__18: 8 PC
 SG_ P2D_BUCK_PHY_RX_Byte1_18 : 0|8@1+ (1,0) [0|255] ""  DCDC
 SG_ P2D_BUCK_PHY_RX_Byte2_18 : 8|8@1+ (1,0) [0|255] ""  DCDC
 SG_ P2D_BUCK_PHY_RX_Byte3_18 : 16|8@1+ (1,0) [0|255] ""  DCDC
 SG_ P2D_BUCK_PHY_RX_Byte4_18 : 24|8@1+ (1,0) [0|255] ""  DCDC
 SG_ P2D_BUCK_PHY_RX_Byte5_18 : 32|8@1+ (1,0) [0|255] ""  DCDC
 SG_ P2D_BUCK_PHY_RX_Byte6_18 : 40|8@1+ (1,0) [0|255] ""  DCDC
 SG_ P2D_BUCK_PHY_RX_Byte7_18 : 48|8@1+ (1,0) [0|255] ""  DCDC
 SG_ P2D_BUCK_PHY_RX_Byte8_18 : 56|8@1+ (1,0) [0|255] ""  DCDC

BO_ 2149023571 P2D_BUCK_PHY_RX__19: 8 PC
 SG_ P2D_BUCK_PHY_RX_Byte1_19 : 0|8@1+ (1,0) [0|255] ""  DCDC
 SG_ P2D_BUCK_PHY_RX_Byte2_19 : 8|8@1+ (1,0) [0|255] ""  DCDC
 SG_ P2D_BUCK_PHY_RX_Byte3_19 : 16|8@1+ (1,0) [0|255] ""  DCDC
 SG_ P2D_BUCK_PHY_RX_Byte4_19 : 24|8@1+ (1,0) [0|255] ""  DCDC
 SG_ P2D_BUCK_PHY_RX_Byte5_19 : 32|8@1+ (1,0) [0|255] ""  DCDC
 SG_ P2D_BUCK_PHY_RX_Byte6_19 : 40|8@1+ (1,0) [0|255] ""  DCDC
 SG_ P2D_BUCK_PHY_RX_Byte7_19 : 48|8@1+ (1,0) [0|255] ""  DCDC
 SG_ P2D_BUCK_PHY_RX_Byte8_19 : 56|8@1+ (1,0) [0|255] ""  DCDC

BO_ 2149023572 P2D_BUCK_PHY_RX__20: 8 PC
 SG_ P2D_BUCK_PHY_RX_Byte1_20 : 0|8@1+ (1,0) [0|255] ""  DCDC
 SG_ P2D_BUCK_PHY_RX_Byte2_20 : 8|8@1+ (1,0) [0|255] ""  DCDC
 SG_ P2D_BUCK_PHY_RX_Byte3_20 : 16|8@1+ (1,0) [0|255] ""  DCDC
 SG_ P2D_BUCK_PHY_RX_Byte4_20 : 24|8@1+ (1,0) [0|255] ""  DCDC
 SG_ P2D_BUCK_PHY_RX_Byte5_20 : 32|8@1+ (1,0) [0|255] ""  DCDC
 SG_ P2D_BUCK_PHY_RX_Byte6_20 : 40|8@1+ (1,0) [0|255] ""  DCDC
 SG_ P2D_BUCK_PHY_RX_Byte7_20 : 48|8@1+ (1,0) [0|255] ""  DCDC
 SG_ P2D_BUCK_PHY_RX_Byte8_20 : 56|8@1+ (1,0) [0|255] ""  DCDC

BO_ 2149023573 P2D_BUCK_PHY_RX__21: 8 PC
 SG_ P2D_BUCK_PHY_RX_Byte1_21 : 0|8@1+ (1,0) [0|255] ""  DCDC
 SG_ P2D_BUCK_PHY_RX_Byte2_21 : 8|8@1+ (1,0) [0|255] ""  DCDC
 SG_ P2D_BUCK_PHY_RX_Byte3_21 : 16|8@1+ (1,0) [0|255] ""  DCDC
 SG_ P2D_BUCK_PHY_RX_Byte4_21 : 24|8@1+ (1,0) [0|255] ""  DCDC
 SG_ P2D_BUCK_PHY_RX_Byte5_21 : 32|8@1+ (1,0) [0|255] ""  DCDC
 SG_ P2D_BUCK_PHY_RX_Byte6_21 : 40|8@1+ (1,0) [0|255] ""  DCDC
 SG_ P2D_BUCK_PHY_RX_Byte7_21 : 48|8@1+ (1,0) [0|255] ""  DCDC
 SG_ P2D_BUCK_PHY_RX_Byte8_21 : 56|8@1+ (1,0) [0|255] ""  DCDC

BO_ 2149023574 P2D_BUCK_PHY_RX__22: 8 PC
 SG_ P2D_BUCK_PHY_RX_Byte1_22 : 0|8@1+ (1,0) [0|255] ""  DCDC
 SG_ P2D_BUCK_PHY_RX_Byte2_22 : 8|8@1+ (1,0) [0|255] ""  DCDC
 SG_ P2D_BUCK_PHY_RX_Byte3_22 : 16|8@1+ (1,0) [0|255] ""  DCDC
 SG_ P2D_BUCK_PHY_RX_Byte4_22 : 24|8@1+ (1,0) [0|255] ""  DCDC
 SG_ P2D_BUCK_PHY_RX_Byte5_22 : 32|8@1+ (1,0) [0|255] ""  DCDC
 SG_ P2D_BUCK_PHY_RX_Byte6_22 : 40|8@1+ (1,0) [0|255] ""  DCDC
 SG_ P2D_BUCK_PHY_RX_Byte7_22 : 48|8@1+ (1,0) [0|255] ""  DCDC
 SG_ P2D_BUCK_PHY_RX_Byte8_22 : 56|8@1+ (1,0) [0|255] ""  DCDC

BO_ 2149023575 P2D_BUCK_PHY_RX__23: 8 PC
 SG_ P2D_BUCK_PHY_RX_Byte1_23 : 0|8@1+ (1,0) [0|255] ""  DCDC
 SG_ P2D_BUCK_PHY_RX_Byte2_23 : 8|8@1+ (1,0) [0|255] ""  DCDC
 SG_ P2D_BUCK_PHY_RX_Byte3_23 : 16|8@1+ (1,0) [0|255] ""  DCDC
 SG_ P2D_BUCK_PHY_RX_Byte4_23 : 24|8@1+ (1,0) [0|255] ""  DCDC
 SG_ P2D_BUCK_PHY_RX_Byte5_23 : 32|8@1+ (1,0) [0|255] ""  DCDC
 SG_ P2D_BUCK_PHY_RX_Byte6_23 : 40|8@1+ (1,0) [0|255] ""  DCDC
 SG_ P2D_BUCK_PHY_RX_Byte7_23 : 48|8@1+ (1,0) [0|255] ""  DCDC
 SG_ P2D_BUCK_PHY_RX_Byte8_23 : 56|8@1+ (1,0) [0|255] ""  DCDC

BO_ 2149023576 P2D_BUCK_PHY_RX__24: 8 PC
 SG_ P2D_BUCK_PHY_RX_Byte1_24 : 0|8@1+ (1,0) [0|255] ""  DCDC
 SG_ P2D_BUCK_PHY_RX_Byte2_24 : 8|8@1+ (1,0) [0|255] ""  DCDC
 SG_ P2D_BUCK_PHY_RX_Byte3_24 : 16|8@1+ (1,0) [0|255] ""  DCDC
 SG_ P2D_BUCK_PHY_RX_Byte4_24 : 24|8@1+ (1,0) [0|255] ""  DCDC
 SG_ P2D_BUCK_PHY_RX_Byte5_24 : 32|8@1+ (1,0) [0|255] ""  DCDC
 SG_ P2D_BUCK_PHY_RX_Byte6_24 : 40|8@1+ (1,0) [0|255] ""  DCDC
 SG_ P2D_BUCK_PHY_RX_Byte7_24 : 48|8@1+ (1,0) [0|255] ""  DCDC
 SG_ P2D_BUCK_PHY_RX_Byte8_24 : 56|8@1+ (1,0) [0|255] ""  DCDC

BO_ 2149023577 P2D_BUCK_PHY_RX__25: 8 PC
 SG_ P2D_BUCK_PHY_RX_Byte1_25 : 0|8@1+ (1,0) [0|255] ""  DCDC
 SG_ P2D_BUCK_PHY_RX_Byte2_25 : 8|8@1+ (1,0) [0|255] ""  DCDC
 SG_ P2D_BUCK_PHY_RX_Byte3_25 : 16|8@1+ (1,0) [0|255] ""  DCDC
 SG_ P2D_BUCK_PHY_RX_Byte4_25 : 24|8@1+ (1,0) [0|255] ""  DCDC
 SG_ P2D_BUCK_PHY_RX_Byte5_25 : 32|8@1+ (1,0) [0|255] ""  DCDC
 SG_ P2D_BUCK_PHY_RX_Byte6_25 : 40|8@1+ (1,0) [0|255] ""  DCDC
 SG_ P2D_BUCK_PHY_RX_Byte7_25 : 48|8@1+ (1,0) [0|255] ""  DCDC
 SG_ P2D_BUCK_PHY_RX_Byte8_25 : 56|8@1+ (1,0) [0|255] ""  DCDC

BO_ 2149023578 P2D_BUCK_PHY_RX__26: 8 PC
 SG_ P2D_BUCK_PHY_RX_Byte1_26 : 0|8@1+ (1,0) [0|255] ""  DCDC
 SG_ P2D_BUCK_PHY_RX_Byte2_26 : 8|8@1+ (1,0) [0|255] ""  DCDC
 SG_ P2D_BUCK_PHY_RX_Byte3_26 : 16|8@1+ (1,0) [0|255] ""  DCDC
 SG_ P2D_BUCK_PHY_RX_Byte4_26 : 24|8@1+ (1,0) [0|255] ""  DCDC
 SG_ P2D_BUCK_PHY_RX_Byte5_26 : 32|8@1+ (1,0) [0|255] ""  DCDC
 SG_ P2D_BUCK_PHY_RX_Byte6_26 : 40|8@1+ (1,0) [0|255] ""  DCDC
 SG_ P2D_BUCK_PHY_RX_Byte7_26 : 48|8@1+ (1,0) [0|255] ""  DCDC
 SG_ P2D_BUCK_PHY_RX_Byte8_26 : 56|8@1+ (1,0) [0|255] ""  DCDC

BO_ 2149023579 P2D_BUCK_PHY_RX__27: 8 PC
 SG_ P2D_BUCK_PHY_RX_Byte1_27 : 0|8@1+ (1,0) [0|255] ""  DCDC
 SG_ P2D_BUCK_PHY_RX_Byte2_27 : 8|8@1+ (1,0) [0|255] ""  DCDC
 SG_ P2D_BUCK_PHY_RX_Byte3_27 : 16|8@1+ (1,0) [0|255] ""  DCDC
 SG_ P2D_BUCK_PHY_RX_Byte4_27 : 24|8@1+ (1,0) [0|255] ""  DCDC
 SG_ P2D_BUCK_PHY_RX_Byte5_27 : 32|8@1+ (1,0) [0|255] ""  DCDC
 SG_ P2D_BUCK_PHY_RX_Byte6_27 : 40|8@1+ (1,0) [0|255] ""  DCDC
 SG_ P2D_BUCK_PHY_RX_Byte7_27 : 48|8@1+ (1,0) [0|255] ""  DCDC
 SG_ P2D_BUCK_PHY_RX_Byte8_27 : 56|8@1+ (1,0) [0|255] ""  DCDC

BO_ 2149023580 P2D_BUCK_PHY_RX__28: 8 PC
 SG_ P2D_BUCK_PHY_RX_Byte1_28 : 0|8@1+ (1,0) [0|255] ""  DCDC
 SG_ P2D_BUCK_PHY_RX_Byte2_28 : 8|8@1+ (1,0) [0|255] ""  DCDC
 SG_ P2D_BUCK_PHY_RX_Byte3_28 : 16|8@1+ (1,0) [0|255] ""  DCDC
 SG_ P2D_BUCK_PHY_RX_Byte4_28 : 24|8@1+ (1,0) [0|255] ""  DCDC
 SG_ P2D_BUCK_PHY_RX_Byte5_28 : 32|8@1+ (1,0) [0|255] ""  DCDC
 SG_ P2D_BUCK_PHY_RX_Byte6_28 : 40|8@1+ (1,0) [0|255] ""  DCDC
 SG_ P2D_BUCK_PHY_RX_Byte7_28 : 48|8@1+ (1,0) [0|255] ""  DCDC
 SG_ P2D_BUCK_PHY_RX_Byte8_28 : 56|8@1+ (1,0) [0|255] ""  DCDC

BO_ 2149023581 P2D_BUCK_PHY_RX__29: 8 PC
 SG_ P2D_BUCK_PHY_RX_Byte1_29 : 0|8@1+ (1,0) [0|255] ""  DCDC
 SG_ P2D_BUCK_PHY_RX_Byte2_29 : 8|8@1+ (1,0) [0|255] ""  DCDC
 SG_ P2D_BUCK_PHY_RX_Byte3_29 : 16|8@1+ (1,0) [0|255] ""  DCDC
 SG_ P2D_BUCK_PHY_RX_Byte4_29 : 24|8@1+ (1,0) [0|255] ""  DCDC
 SG_ P2D_BUCK_PHY_RX_Byte5_29 : 32|8@1+ (1,0) [0|255] ""  DCDC
 SG_ P2D_BUCK_PHY_RX_Byte6_29 : 40|8@1+ (1,0) [0|255] ""  DCDC
 SG_ P2D_BUCK_PHY_RX_Byte7_29 : 48|8@1+ (1,0) [0|255] ""  DCDC
 SG_ P2D_BUCK_PHY_RX_Byte8_29 : 56|8@1+ (1,0) [0|255] ""  DCDC

BO_ 2149023582 P2D_BUCK_PHY_RX__30: 8 PC
 SG_ P2D_BUCK_PHY_RX_Byte1_30 : 0|8@1+ (1,0) [0|255] ""  DCDC
 SG_ P2D_BUCK_PHY_RX_Byte2_30 : 8|8@1+ (1,0) [0|255] ""  DCDC
 SG_ P2D_BUCK_PHY_RX_Byte3_30 : 16|8@1+ (1,0) [0|255] ""  DCDC
 SG_ P2D_BUCK_PHY_RX_Byte4_30 : 24|8@1+ (1,0) [0|255] ""  DCDC
 SG_ P2D_BUCK_PHY_RX_Byte5_30 : 32|8@1+ (1,0) [0|255] ""  DCDC
 SG_ P2D_BUCK_PHY_RX_Byte6_30 : 40|8@1+ (1,0) [0|255] ""  DCDC
 SG_ P2D_BUCK_PHY_RX_Byte7_30 : 48|8@1+ (1,0) [0|255] ""  DCDC
 SG_ P2D_BUCK_PHY_RX_Byte8_30 : 56|8@1+ (1,0) [0|255] ""  DCDC

BO_ 2149023583 P2D_BUCK_PHY_RX__31: 8 PC
 SG_ P2D_BUCK_PHY_RX_Byte1_31 : 0|8@1+ (1,0) [0|255] ""  DCDC
 SG_ P2D_BUCK_PHY_RX_Byte2_31 : 8|8@1+ (1,0) [0|255] ""  DCDC
 SG_ P2D_BUCK_PHY_RX_Byte3_31 : 16|8@1+ (1,0) [0|255] ""  DCDC
 SG_ P2D_BUCK_PHY_RX_Byte4_31 : 24|8@1+ (1,0) [0|255] ""  DCDC
 SG_ P2D_BUCK_PHY_RX_Byte5_31 : 32|8@1+ (1,0) [0|255] ""  DCDC
 SG_ P2D_BUCK_PHY_RX_Byte6_31 : 40|8@1+ (1,0) [0|255] ""  DCDC
 SG_ P2D_BUCK_PHY_RX_Byte7_31 : 48|8@1+ (1,0) [0|255] ""  DCDC
 SG_ P2D_BUCK_PHY_RX_Byte8_31 : 56|8@1+ (1,0) [0|255] ""  DCDC

BO_ 2149023584 P2D_BUCK_PHY_RX__32: 8 PC
 SG_ P2D_BUCK_PHY_RX_Byte1_32 : 0|8@1+ (1,0) [0|255] ""  DCDC
 SG_ P2D_BUCK_PHY_RX_Byte2_32 : 8|8@1+ (1,0) [0|255] ""  DCDC
 SG_ P2D_BUCK_PHY_RX_Byte3_32 : 16|8@1+ (1,0) [0|255] ""  DCDC
 SG_ P2D_BUCK_PHY_RX_Byte4_32 : 24|8@1+ (1,0) [0|255] ""  DCDC
 SG_ P2D_BUCK_PHY_RX_Byte5_32 : 32|8@1+ (1,0) [0|255] ""  DCDC
 SG_ P2D_BUCK_PHY_RX_Byte6_32 : 40|8@1+ (1,0) [0|255] ""  DCDC
 SG_ P2D_BUCK_PHY_RX_Byte7_32 : 48|8@1+ (1,0) [0|255] ""  DCDC
 SG_ P2D_BUCK_PHY_RX_Byte8_32 : 56|8@1+ (1,0) [0|255] ""  DCDC

BO_ 2149023585 P2D_BUCK_PHY_RX__33: 8 PC
 SG_ P2D_BUCK_PHY_RX_Byte1_33 : 0|8@1+ (1,0) [0|255] ""  DCDC
 SG_ P2D_BUCK_PHY_RX_Byte2_33 : 8|8@1+ (1,0) [0|255] ""  DCDC
 SG_ P2D_BUCK_PHY_RX_Byte3_33 : 16|8@1+ (1,0) [0|255] ""  DCDC
 SG_ P2D_BUCK_PHY_RX_Byte4_33 : 24|8@1+ (1,0) [0|255] ""  DCDC
 SG_ P2D_BUCK_PHY_RX_Byte5_33 : 32|8@1+ (1,0) [0|255] ""  DCDC
 SG_ P2D_BUCK_PHY_RX_Byte6_33 : 40|8@1+ (1,0) [0|255] ""  DCDC
 SG_ P2D_BUCK_PHY_RX_Byte7_33 : 48|8@1+ (1,0) [0|255] ""  DCDC
 SG_ P2D_BUCK_PHY_RX_Byte8_33 : 56|8@1+ (1,0) [0|255] ""  DCDC

BO_ 2149023586 P2D_BUCK_PHY_RX__34: 8 PC
 SG_ P2D_BUCK_PHY_RX_Byte1_34 : 0|8@1+ (1,0) [0|255] ""  DCDC
 SG_ P2D_BUCK_PHY_RX_Byte2_34 : 8|8@1+ (1,0) [0|255] ""  DCDC
 SG_ P2D_BUCK_PHY_RX_Byte3_34 : 16|8@1+ (1,0) [0|255] ""  DCDC
 SG_ P2D_BUCK_PHY_RX_Byte4_34 : 24|8@1+ (1,0) [0|255] ""  DCDC
 SG_ P2D_BUCK_PHY_RX_Byte5_34 : 32|8@1+ (1,0) [0|255] ""  DCDC
 SG_ P2D_BUCK_PHY_RX_Byte6_34 : 40|8@1+ (1,0) [0|255] ""  DCDC
 SG_ P2D_BUCK_PHY_RX_Byte7_34 : 48|8@1+ (1,0) [0|255] ""  DCDC
 SG_ P2D_BUCK_PHY_RX_Byte8_34 : 56|8@1+ (1,0) [0|255] ""  DCDC

BO_ 2149023587 P2D_BUCK_PHY_RX__35: 8 PC
 SG_ P2D_BUCK_PHY_RX_Byte1_35 : 0|8@1+ (1,0) [0|255] ""  DCDC
 SG_ P2D_BUCK_PHY_RX_Byte2_35 : 8|8@1+ (1,0) [0|255] ""  DCDC
 SG_ P2D_BUCK_PHY_RX_Byte3_35 : 16|8@1+ (1,0) [0|255] ""  DCDC
 SG_ P2D_BUCK_PHY_RX_Byte4_35 : 24|8@1+ (1,0) [0|255] ""  DCDC
 SG_ P2D_BUCK_PHY_RX_Byte5_35 : 32|8@1+ (1,0) [0|255] ""  DCDC
 SG_ P2D_BUCK_PHY_RX_Byte6_35 : 40|8@1+ (1,0) [0|255] ""  DCDC
 SG_ P2D_BUCK_PHY_RX_Byte7_35 : 48|8@1+ (1,0) [0|255] ""  DCDC
 SG_ P2D_BUCK_PHY_RX_Byte8_35 : 56|8@1+ (1,0) [0|255] ""  DCDC

BO_ 2149023588 P2D_BUCK_PHY_RX__36: 8 PC
 SG_ P2D_BUCK_PHY_RX_Byte1_36 : 0|8@1+ (1,0) [0|255] ""  DCDC
 SG_ P2D_BUCK_PHY_RX_Byte2_36 : 8|8@1+ (1,0) [0|255] ""  DCDC
 SG_ P2D_BUCK_PHY_RX_Byte3_36 : 16|8@1+ (1,0) [0|255] ""  DCDC
 SG_ P2D_BUCK_PHY_RX_Byte4_36 : 24|8@1+ (1,0) [0|255] ""  DCDC
 SG_ P2D_BUCK_PHY_RX_Byte5_36 : 32|8@1+ (1,0) [0|255] ""  DCDC
 SG_ P2D_BUCK_PHY_RX_Byte6_36 : 40|8@1+ (1,0) [0|255] ""  DCDC
 SG_ P2D_BUCK_PHY_RX_Byte7_36 : 48|8@1+ (1,0) [0|255] ""  DCDC
 SG_ P2D_BUCK_PHY_RX_Byte8_36 : 56|8@1+ (1,0) [0|255] ""  DCDC

BO_ 2149023589 P2D_BUCK_PHY_RX__37: 8 PC
 SG_ P2D_BUCK_PHY_RX_Byte1_37 : 0|8@1+ (1,0) [0|255] ""  DCDC
 SG_ P2D_BUCK_PHY_RX_Byte2_37 : 8|8@1+ (1,0) [0|255] ""  DCDC
 SG_ P2D_BUCK_PHY_RX_Byte3_37 : 16|8@1+ (1,0) [0|255] ""  DCDC
 SG_ P2D_BUCK_PHY_RX_Byte4_37 : 24|8@1+ (1,0) [0|255] ""  DCDC
 SG_ P2D_BUCK_PHY_RX_Byte5_37 : 32|8@1+ (1,0) [0|255] ""  DCDC
 SG_ P2D_BUCK_PHY_RX_Byte6_37 : 40|8@1+ (1,0) [0|255] ""  DCDC
 SG_ P2D_BUCK_PHY_RX_Byte7_37 : 48|8@1+ (1,0) [0|255] ""  DCDC
 SG_ P2D_BUCK_PHY_RX_Byte8_37 : 56|8@1+ (1,0) [0|255] ""  DCDC

BO_ 2149023590 P2D_BUCK_PHY_RX__38: 8 PC
 SG_ P2D_BUCK_PHY_RX_Byte1_38 : 0|8@1+ (1,0) [0|255] ""  DCDC
 SG_ P2D_BUCK_PHY_RX_Byte2_38 : 8|8@1+ (1,0) [0|255] ""  DCDC
 SG_ P2D_BUCK_PHY_RX_Byte3_38 : 16|8@1+ (1,0) [0|255] ""  DCDC
 SG_ P2D_BUCK_PHY_RX_Byte4_38 : 24|8@1+ (1,0) [0|255] ""  DCDC
 SG_ P2D_BUCK_PHY_RX_Byte5_38 : 32|8@1+ (1,0) [0|255] ""  DCDC
 SG_ P2D_BUCK_PHY_RX_Byte6_38 : 40|8@1+ (1,0) [0|255] ""  DCDC
 SG_ P2D_BUCK_PHY_RX_Byte7_38 : 48|8@1+ (1,0) [0|255] ""  DCDC
 SG_ P2D_BUCK_PHY_RX_Byte8_38 : 56|8@1+ (1,0) [0|255] ""  DCDC

BO_ 2149023591 P2D_BUCK_PHY_RX__39: 8 PC
 SG_ P2D_BUCK_PHY_RX_Byte1_39 : 0|8@1+ (1,0) [0|255] ""  DCDC
 SG_ P2D_BUCK_PHY_RX_Byte2_39 : 8|8@1+ (1,0) [0|255] ""  DCDC
 SG_ P2D_BUCK_PHY_RX_Byte3_39 : 16|8@1+ (1,0) [0|255] ""  DCDC
 SG_ P2D_BUCK_PHY_RX_Byte4_39 : 24|8@1+ (1,0) [0|255] ""  DCDC
 SG_ P2D_BUCK_PHY_RX_Byte5_39 : 32|8@1+ (1,0) [0|255] ""  DCDC
 SG_ P2D_BUCK_PHY_RX_Byte6_39 : 40|8@1+ (1,0) [0|255] ""  DCDC
 SG_ P2D_BUCK_PHY_RX_Byte7_39 : 48|8@1+ (1,0) [0|255] ""  DCDC
 SG_ P2D_BUCK_PHY_RX_Byte8_39 : 56|8@1+ (1,0) [0|255] ""  DCDC

BO_ 2149023592 P2D_BUCK_PHY_RX__40: 8 PC
 SG_ P2D_BUCK_PHY_RX_Byte1_40 : 0|8@1+ (1,0) [0|255] ""  DCDC
 SG_ P2D_BUCK_PHY_RX_Byte2_40 : 8|8@1+ (1,0) [0|255] ""  DCDC
 SG_ P2D_BUCK_PHY_RX_Byte3_40 : 16|8@1+ (1,0) [0|255] ""  DCDC
 SG_ P2D_BUCK_PHY_RX_Byte4_40 : 24|8@1+ (1,0) [0|255] ""  DCDC
 SG_ P2D_BUCK_PHY_RX_Byte5_40 : 32|8@1+ (1,0) [0|255] ""  DCDC
 SG_ P2D_BUCK_PHY_RX_Byte6_40 : 40|8@1+ (1,0) [0|255] ""  DCDC
 SG_ P2D_BUCK_PHY_RX_Byte7_40 : 48|8@1+ (1,0) [0|255] ""  DCDC
 SG_ P2D_BUCK_PHY_RX_Byte8_40 : 56|8@1+ (1,0) [0|255] ""  DCDC

BO_ 2149023593 P2D_BUCK_PHY_RX__41: 8 PC
 SG_ P2D_BUCK_PHY_RX_Byte1_41 : 0|8@1+ (1,0) [0|255] ""  DCDC
 SG_ P2D_BUCK_PHY_RX_Byte2_41 : 8|8@1+ (1,0) [0|255] ""  DCDC
 SG_ P2D_BUCK_PHY_RX_Byte3_41 : 16|8@1+ (1,0) [0|255] ""  DCDC
 SG_ P2D_BUCK_PHY_RX_Byte4_41 : 24|8@1+ (1,0) [0|255] ""  DCDC
 SG_ P2D_BUCK_PHY_RX_Byte5_41 : 32|8@1+ (1,0) [0|255] ""  DCDC
 SG_ P2D_BUCK_PHY_RX_Byte6_41 : 40|8@1+ (1,0) [0|255] ""  DCDC
 SG_ P2D_BUCK_PHY_RX_Byte7_41 : 48|8@1+ (1,0) [0|255] ""  DCDC
 SG_ P2D_BUCK_PHY_RX_Byte8_41 : 56|8@1+ (1,0) [0|255] ""  DCDC

BO_ 2149023594 P2D_BUCK_PHY_RX__42: 8 PC
 SG_ P2D_BUCK_PHY_RX_Byte1_42 : 0|8@1+ (1,0) [0|255] ""  DCDC
 SG_ P2D_BUCK_PHY_RX_Byte2_42 : 8|8@1+ (1,0) [0|255] ""  DCDC
 SG_ P2D_BUCK_PHY_RX_Byte3_42 : 16|8@1+ (1,0) [0|255] ""  DCDC
 SG_ P2D_BUCK_PHY_RX_Byte4_42 : 24|8@1+ (1,0) [0|255] ""  DCDC
 SG_ P2D_BUCK_PHY_RX_Byte5_42 : 32|8@1+ (1,0) [0|255] ""  DCDC
 SG_ P2D_BUCK_PHY_RX_Byte6_42 : 40|8@1+ (1,0) [0|255] ""  DCDC
 SG_ P2D_BUCK_PHY_RX_Byte7_42 : 48|8@1+ (1,0) [0|255] ""  DCDC
 SG_ P2D_BUCK_PHY_RX_Byte8_42 : 56|8@1+ (1,0) [0|255] ""  DCDC

BO_ 2149023595 P2D_BUCK_PHY_RX__43: 8 PC
 SG_ P2D_BUCK_PHY_RX_Byte1_43 : 0|8@1+ (1,0) [0|255] ""  DCDC
 SG_ P2D_BUCK_PHY_RX_Byte2_43 : 8|8@1+ (1,0) [0|255] ""  DCDC
 SG_ P2D_BUCK_PHY_RX_Byte3_43 : 16|8@1+ (1,0) [0|255] ""  DCDC
 SG_ P2D_BUCK_PHY_RX_Byte4_43 : 24|8@1+ (1,0) [0|255] ""  DCDC
 SG_ P2D_BUCK_PHY_RX_Byte5_43 : 32|8@1+ (1,0) [0|255] ""  DCDC
 SG_ P2D_BUCK_PHY_RX_Byte6_43 : 40|8@1+ (1,0) [0|255] ""  DCDC
 SG_ P2D_BUCK_PHY_RX_Byte7_43 : 48|8@1+ (1,0) [0|255] ""  DCDC
 SG_ P2D_BUCK_PHY_RX_Byte8_43 : 56|8@1+ (1,0) [0|255] ""  DCDC

BO_ 2149023596 P2D_BUCK_PHY_RX__44: 8 PC
 SG_ P2D_BUCK_PHY_RX_Byte1_44 : 0|8@1+ (1,0) [0|255] ""  DCDC
 SG_ P2D_BUCK_PHY_RX_Byte2_44 : 8|8@1+ (1,0) [0|255] ""  DCDC
 SG_ P2D_BUCK_PHY_RX_Byte3_44 : 16|8@1+ (1,0) [0|255] ""  DCDC
 SG_ P2D_BUCK_PHY_RX_Byte4_44 : 24|8@1+ (1,0) [0|255] ""  DCDC
 SG_ P2D_BUCK_PHY_RX_Byte5_44 : 32|8@1+ (1,0) [0|255] ""  DCDC
 SG_ P2D_BUCK_PHY_RX_Byte6_44 : 40|8@1+ (1,0) [0|255] ""  DCDC
 SG_ P2D_BUCK_PHY_RX_Byte7_44 : 48|8@1+ (1,0) [0|255] ""  DCDC
 SG_ P2D_BUCK_PHY_RX_Byte8_44 : 56|8@1+ (1,0) [0|255] ""  DCDC

BO_ 2149023597 P2D_BUCK_PHY_RX__45: 8 PC
 SG_ P2D_BUCK_PHY_RX_Byte1_45 : 0|8@1+ (1,0) [0|255] ""  DCDC
 SG_ P2D_BUCK_PHY_RX_Byte2_45 : 8|8@1+ (1,0) [0|255] ""  DCDC
 SG_ P2D_BUCK_PHY_RX_Byte3_45 : 16|8@1+ (1,0) [0|255] ""  DCDC
 SG_ P2D_BUCK_PHY_RX_Byte4_45 : 24|8@1+ (1,0) [0|255] ""  DCDC
 SG_ P2D_BUCK_PHY_RX_Byte5_45 : 32|8@1+ (1,0) [0|255] ""  DCDC
 SG_ P2D_BUCK_PHY_RX_Byte6_45 : 40|8@1+ (1,0) [0|255] ""  DCDC
 SG_ P2D_BUCK_PHY_RX_Byte7_45 : 48|8@1+ (1,0) [0|255] ""  DCDC
 SG_ P2D_BUCK_PHY_RX_Byte8_45 : 56|8@1+ (1,0) [0|255] ""  DCDC

BO_ 2149023598 P2D_BUCK_PHY_RX__46: 8 PC
 SG_ P2D_BUCK_PHY_RX_Byte1_46 : 0|8@1+ (1,0) [0|255] ""  DCDC
 SG_ P2D_BUCK_PHY_RX_Byte2_46 : 8|8@1+ (1,0) [0|255] ""  DCDC
 SG_ P2D_BUCK_PHY_RX_Byte3_46 : 16|8@1+ (1,0) [0|255] ""  DCDC
 SG_ P2D_BUCK_PHY_RX_Byte4_46 : 24|8@1+ (1,0) [0|255] ""  DCDC
 SG_ P2D_BUCK_PHY_RX_Byte5_46 : 32|8@1+ (1,0) [0|255] ""  DCDC
 SG_ P2D_BUCK_PHY_RX_Byte6_46 : 40|8@1+ (1,0) [0|255] ""  DCDC
 SG_ P2D_BUCK_PHY_RX_Byte7_46 : 48|8@1+ (1,0) [0|255] ""  DCDC
 SG_ P2D_BUCK_PHY_RX_Byte8_46 : 56|8@1+ (1,0) [0|255] ""  DCDC

BO_ 2149023599 P2D_BUCK_PHY_RX__47: 8 PC
 SG_ P2D_BUCK_PHY_RX_Byte1_47 : 0|8@1+ (1,0) [0|255] ""  DCDC
 SG_ P2D_BUCK_PHY_RX_Byte2_47 : 8|8@1+ (1,0) [0|255] ""  DCDC
 SG_ P2D_BUCK_PHY_RX_Byte3_47 : 16|8@1+ (1,0) [0|255] ""  DCDC
 SG_ P2D_BUCK_PHY_RX_Byte4_47 : 24|8@1+ (1,0) [0|255] ""  DCDC
 SG_ P2D_BUCK_PHY_RX_Byte5_47 : 32|8@1+ (1,0) [0|255] ""  DCDC
 SG_ P2D_BUCK_PHY_RX_Byte6_47 : 40|8@1+ (1,0) [0|255] ""  DCDC
 SG_ P2D_BUCK_PHY_RX_Byte7_47 : 48|8@1+ (1,0) [0|255] ""  DCDC
 SG_ P2D_BUCK_PHY_RX_Byte8_47 : 56|8@1+ (1,0) [0|255] ""  DCDC

BO_ 2149023600 P2D_BUCK_PHY_RX__48: 8 PC
 SG_ P2D_BUCK_PHY_RX_Byte1_48 : 0|8@1+ (1,0) [0|255] ""  DCDC
 SG_ P2D_BUCK_PHY_RX_Byte2_48 : 8|8@1+ (1,0) [0|255] ""  DCDC
 SG_ P2D_BUCK_PHY_RX_Byte3_48 : 16|8@1+ (1,0) [0|255] ""  DCDC
 SG_ P2D_BUCK_PHY_RX_Byte4_48 : 24|8@1+ (1,0) [0|255] ""  DCDC
 SG_ P2D_BUCK_PHY_RX_Byte5_48 : 32|8@1+ (1,0) [0|255] ""  DCDC
 SG_ P2D_BUCK_PHY_RX_Byte6_48 : 40|8@1+ (1,0) [0|255] ""  DCDC
 SG_ P2D_BUCK_PHY_RX_Byte7_48 : 48|8@1+ (1,0) [0|255] ""  DCDC
 SG_ P2D_BUCK_PHY_RX_Byte8_48 : 56|8@1+ (1,0) [0|255] ""  DCDC

BO_ 2149023601 P2D_BUCK_PHY_RX__49: 8 PC
 SG_ P2D_BUCK_PHY_RX_Byte1_49 : 0|8@1+ (1,0) [0|255] ""  DCDC
 SG_ P2D_BUCK_PHY_RX_Byte2_49 : 8|8@1+ (1,0) [0|255] ""  DCDC
 SG_ P2D_BUCK_PHY_RX_Byte3_49 : 16|8@1+ (1,0) [0|255] ""  DCDC
 SG_ P2D_BUCK_PHY_RX_Byte4_49 : 24|8@1+ (1,0) [0|255] ""  DCDC
 SG_ P2D_BUCK_PHY_RX_Byte5_49 : 32|8@1+ (1,0) [0|255] ""  DCDC
 SG_ P2D_BUCK_PHY_RX_Byte6_49 : 40|8@1+ (1,0) [0|255] ""  DCDC
 SG_ P2D_BUCK_PHY_RX_Byte7_49 : 48|8@1+ (1,0) [0|255] ""  DCDC
 SG_ P2D_BUCK_PHY_RX_Byte8_49 : 56|8@1+ (1,0) [0|255] ""  DCDC

BO_ 2149023602 P2D_BUCK_PHY_RX__50: 8 PC
 SG_ P2D_BUCK_PHY_RX_Byte1_50 : 0|8@1+ (1,0) [0|255] ""  DCDC
 SG_ P2D_BUCK_PHY_RX_Byte2_50 : 8|8@1+ (1,0) [0|255] ""  DCDC
 SG_ P2D_BUCK_PHY_RX_Byte3_50 : 16|8@1+ (1,0) [0|255] ""  DCDC
 SG_ P2D_BUCK_PHY_RX_Byte4_50 : 24|8@1+ (1,0) [0|255] ""  DCDC
 SG_ P2D_BUCK_PHY_RX_Byte5_50 : 32|8@1+ (1,0) [0|255] ""  DCDC
 SG_ P2D_BUCK_PHY_RX_Byte6_50 : 40|8@1+ (1,0) [0|255] ""  DCDC
 SG_ P2D_BUCK_PHY_RX_Byte7_50 : 48|8@1+ (1,0) [0|255] ""  DCDC
 SG_ P2D_BUCK_PHY_RX_Byte8_50 : 56|8@1+ (1,0) [0|255] ""  DCDC

BO_ 2149023603 P2D_BUCK_PHY_RX__51: 8 PC
 SG_ P2D_BUCK_PHY_RX_Byte1_51 : 0|8@1+ (1,0) [0|255] ""  DCDC
 SG_ P2D_BUCK_PHY_RX_Byte2_51 : 8|8@1+ (1,0) [0|255] ""  DCDC
 SG_ P2D_BUCK_PHY_RX_Byte3_51 : 16|8@1+ (1,0) [0|255] ""  DCDC
 SG_ P2D_BUCK_PHY_RX_Byte4_51 : 24|8@1+ (1,0) [0|255] ""  DCDC
 SG_ P2D_BUCK_PHY_RX_Byte5_51 : 32|8@1+ (1,0) [0|255] ""  DCDC
 SG_ P2D_BUCK_PHY_RX_Byte6_51 : 40|8@1+ (1,0) [0|255] ""  DCDC
 SG_ P2D_BUCK_PHY_RX_Byte7_51 : 48|8@1+ (1,0) [0|255] ""  DCDC
 SG_ P2D_BUCK_PHY_RX_Byte8_51 : 56|8@1+ (1,0) [0|255] ""  DCDC

BO_ 2149023604 P2D_BUCK_PHY_RX__52: 8 PC
 SG_ P2D_BUCK_PHY_RX_Byte1_52 : 0|8@1+ (1,0) [0|255] ""  DCDC
 SG_ P2D_BUCK_PHY_RX_Byte2_52 : 8|8@1+ (1,0) [0|255] ""  DCDC
 SG_ P2D_BUCK_PHY_RX_Byte3_52 : 16|8@1+ (1,0) [0|255] ""  DCDC
 SG_ P2D_BUCK_PHY_RX_Byte4_52 : 24|8@1+ (1,0) [0|255] ""  DCDC
 SG_ P2D_BUCK_PHY_RX_Byte5_52 : 32|8@1+ (1,0) [0|255] ""  DCDC
 SG_ P2D_BUCK_PHY_RX_Byte6_52 : 40|8@1+ (1,0) [0|255] ""  DCDC
 SG_ P2D_BUCK_PHY_RX_Byte7_52 : 48|8@1+ (1,0) [0|255] ""  DCDC
 SG_ P2D_BUCK_PHY_RX_Byte8_52 : 56|8@1+ (1,0) [0|255] ""  DCDC

BO_ 2149023605 P2D_BUCK_PHY_RX__53: 8 PC
 SG_ P2D_BUCK_PHY_RX_Byte1_53 : 0|8@1+ (1,0) [0|255] ""  DCDC
 SG_ P2D_BUCK_PHY_RX_Byte2_53 : 8|8@1+ (1,0) [0|255] ""  DCDC
 SG_ P2D_BUCK_PHY_RX_Byte3_53 : 16|8@1+ (1,0) [0|255] ""  DCDC
 SG_ P2D_BUCK_PHY_RX_Byte4_53 : 24|8@1+ (1,0) [0|255] ""  DCDC
 SG_ P2D_BUCK_PHY_RX_Byte5_53 : 32|8@1+ (1,0) [0|255] ""  DCDC
 SG_ P2D_BUCK_PHY_RX_Byte6_53 : 40|8@1+ (1,0) [0|255] ""  DCDC
 SG_ P2D_BUCK_PHY_RX_Byte7_53 : 48|8@1+ (1,0) [0|255] ""  DCDC
 SG_ P2D_BUCK_PHY_RX_Byte8_53 : 56|8@1+ (1,0) [0|255] ""  DCDC

BO_ 2149023606 P2D_BUCK_PHY_RX__54: 8 PC
 SG_ P2D_BUCK_PHY_RX_Byte1_54 : 0|8@1+ (1,0) [0|255] ""  DCDC
 SG_ P2D_BUCK_PHY_RX_Byte2_54 : 8|8@1+ (1,0) [0|255] ""  DCDC
 SG_ P2D_BUCK_PHY_RX_Byte3_54 : 16|8@1+ (1,0) [0|255] ""  DCDC
 SG_ P2D_BUCK_PHY_RX_Byte4_54 : 24|8@1+ (1,0) [0|255] ""  DCDC
 SG_ P2D_BUCK_PHY_RX_Byte5_54 : 32|8@1+ (1,0) [0|255] ""  DCDC
 SG_ P2D_BUCK_PHY_RX_Byte6_54 : 40|8@1+ (1,0) [0|255] ""  DCDC
 SG_ P2D_BUCK_PHY_RX_Byte7_54 : 48|8@1+ (1,0) [0|255] ""  DCDC
 SG_ P2D_BUCK_PHY_RX_Byte8_54 : 56|8@1+ (1,0) [0|255] ""  DCDC

BO_ 2149023607 P2D_BUCK_PHY_RX__55: 8 PC
 SG_ P2D_BUCK_PHY_RX_Byte1_55 : 0|8@1+ (1,0) [0|255] ""  DCDC
 SG_ P2D_BUCK_PHY_RX_Byte2_55 : 8|8@1+ (1,0) [0|255] ""  DCDC
 SG_ P2D_BUCK_PHY_RX_Byte3_55 : 16|8@1+ (1,0) [0|255] ""  DCDC
 SG_ P2D_BUCK_PHY_RX_Byte4_55 : 24|8@1+ (1,0) [0|255] ""  DCDC
 SG_ P2D_BUCK_PHY_RX_Byte5_55 : 32|8@1+ (1,0) [0|255] ""  DCDC
 SG_ P2D_BUCK_PHY_RX_Byte6_55 : 40|8@1+ (1,0) [0|255] ""  DCDC
 SG_ P2D_BUCK_PHY_RX_Byte7_55 : 48|8@1+ (1,0) [0|255] ""  DCDC
 SG_ P2D_BUCK_PHY_RX_Byte8_55 : 56|8@1+ (1,0) [0|255] ""  DCDC

BO_ 2149023608 P2D_BUCK_PHY_RX__56: 8 PC
 SG_ P2D_BUCK_PHY_RX_Byte1_56 : 0|8@1+ (1,0) [0|255] ""  DCDC
 SG_ P2D_BUCK_PHY_RX_Byte2_56 : 8|8@1+ (1,0) [0|255] ""  DCDC
 SG_ P2D_BUCK_PHY_RX_Byte3_56 : 16|8@1+ (1,0) [0|255] ""  DCDC
 SG_ P2D_BUCK_PHY_RX_Byte4_56 : 24|8@1+ (1,0) [0|255] ""  DCDC
 SG_ P2D_BUCK_PHY_RX_Byte5_56 : 32|8@1+ (1,0) [0|255] ""  DCDC
 SG_ P2D_BUCK_PHY_RX_Byte6_56 : 40|8@1+ (1,0) [0|255] ""  DCDC
 SG_ P2D_BUCK_PHY_RX_Byte7_56 : 48|8@1+ (1,0) [0|255] ""  DCDC
 SG_ P2D_BUCK_PHY_RX_Byte8_56 : 56|8@1+ (1,0) [0|255] ""  DCDC

BO_ 2149023609 P2D_BUCK_PHY_RX__57: 8 PC
 SG_ P2D_BUCK_PHY_RX_Byte1_57 : 0|8@1+ (1,0) [0|255] ""  DCDC
 SG_ P2D_BUCK_PHY_RX_Byte2_57 : 8|8@1+ (1,0) [0|255] ""  DCDC
 SG_ P2D_BUCK_PHY_RX_Byte3_57 : 16|8@1+ (1,0) [0|255] ""  DCDC
 SG_ P2D_BUCK_PHY_RX_Byte4_57 : 24|8@1+ (1,0) [0|255] ""  DCDC
 SG_ P2D_BUCK_PHY_RX_Byte5_57 : 32|8@1+ (1,0) [0|255] ""  DCDC
 SG_ P2D_BUCK_PHY_RX_Byte6_57 : 40|8@1+ (1,0) [0|255] ""  DCDC
 SG_ P2D_BUCK_PHY_RX_Byte7_57 : 48|8@1+ (1,0) [0|255] ""  DCDC
 SG_ P2D_BUCK_PHY_RX_Byte8_57 : 56|8@1+ (1,0) [0|255] ""  DCDC

BO_ 2149023610 P2D_BUCK_PHY_RX__58: 8 PC
 SG_ P2D_BUCK_PHY_RX_Byte1_58 : 0|8@1+ (1,0) [0|255] ""  DCDC
 SG_ P2D_BUCK_PHY_RX_Byte2_58 : 8|8@1+ (1,0) [0|255] ""  DCDC
 SG_ P2D_BUCK_PHY_RX_Byte3_58 : 16|8@1+ (1,0) [0|255] ""  DCDC
 SG_ P2D_BUCK_PHY_RX_Byte4_58 : 24|8@1+ (1,0) [0|255] ""  DCDC
 SG_ P2D_BUCK_PHY_RX_Byte5_58 : 32|8@1+ (1,0) [0|255] ""  DCDC
 SG_ P2D_BUCK_PHY_RX_Byte6_58 : 40|8@1+ (1,0) [0|255] ""  DCDC
 SG_ P2D_BUCK_PHY_RX_Byte7_58 : 48|8@1+ (1,0) [0|255] ""  DCDC
 SG_ P2D_BUCK_PHY_RX_Byte8_58 : 56|8@1+ (1,0) [0|255] ""  DCDC

BO_ 2149023611 P2D_BUCK_PHY_RX__59: 8 PC
 SG_ P2D_BUCK_PHY_RX_Byte1_59 : 0|8@1+ (1,0) [0|255] ""  DCDC
 SG_ P2D_BUCK_PHY_RX_Byte2_59 : 8|8@1+ (1,0) [0|255] ""  DCDC
 SG_ P2D_BUCK_PHY_RX_Byte3_59 : 16|8@1+ (1,0) [0|255] ""  DCDC
 SG_ P2D_BUCK_PHY_RX_Byte4_59 : 24|8@1+ (1,0) [0|255] ""  DCDC
 SG_ P2D_BUCK_PHY_RX_Byte5_59 : 32|8@1+ (1,0) [0|255] ""  DCDC
 SG_ P2D_BUCK_PHY_RX_Byte6_59 : 40|8@1+ (1,0) [0|255] ""  DCDC
 SG_ P2D_BUCK_PHY_RX_Byte7_59 : 48|8@1+ (1,0) [0|255] ""  DCDC
 SG_ P2D_BUCK_PHY_RX_Byte8_59 : 56|8@1+ (1,0) [0|255] ""  DCDC

BO_ 2149023612 P2D_BUCK_PHY_RX__60: 8 PC
 SG_ P2D_BUCK_PHY_RX_Byte1_60 : 0|8@1+ (1,0) [0|255] ""  DCDC
 SG_ P2D_BUCK_PHY_RX_Byte2_60 : 8|8@1+ (1,0) [0|255] ""  DCDC
 SG_ P2D_BUCK_PHY_RX_Byte3_60 : 16|8@1+ (1,0) [0|255] ""  DCDC
 SG_ P2D_BUCK_PHY_RX_Byte4_60 : 24|8@1+ (1,0) [0|255] ""  DCDC
 SG_ P2D_BUCK_PHY_RX_Byte5_60 : 32|8@1+ (1,0) [0|255] ""  DCDC
 SG_ P2D_BUCK_PHY_RX_Byte6_60 : 40|8@1+ (1,0) [0|255] ""  DCDC
 SG_ P2D_BUCK_PHY_RX_Byte7_60 : 48|8@1+ (1,0) [0|255] ""  DCDC
 SG_ P2D_BUCK_PHY_RX_Byte8_60 : 56|8@1+ (1,0) [0|255] ""  DCDC

BO_ 2149023613 P2D_BUCK_PHY_RX__61: 8 PC
 SG_ P2D_BUCK_PHY_RX_Byte1_61 : 0|8@1+ (1,0) [0|255] ""  DCDC
 SG_ P2D_BUCK_PHY_RX_Byte2_61 : 8|8@1+ (1,0) [0|255] ""  DCDC
 SG_ P2D_BUCK_PHY_RX_Byte3_61 : 16|8@1+ (1,0) [0|255] ""  DCDC
 SG_ P2D_BUCK_PHY_RX_Byte4_61 : 24|8@1+ (1,0) [0|255] ""  DCDC
 SG_ P2D_BUCK_PHY_RX_Byte5_61 : 32|8@1+ (1,0) [0|255] ""  DCDC
 SG_ P2D_BUCK_PHY_RX_Byte6_61 : 40|8@1+ (1,0) [0|255] ""  DCDC
 SG_ P2D_BUCK_PHY_RX_Byte7_61 : 48|8@1+ (1,0) [0|255] ""  DCDC
 SG_ P2D_BUCK_PHY_RX_Byte8_61 : 56|8@1+ (1,0) [0|255] ""  DCDC

BO_ 2149023614 P2D_BUCK_PHY_RX__62: 8 PC
 SG_ P2D_BUCK_PHY_RX_Byte1_62 : 0|8@1+ (1,0) [0|255] ""  DCDC
 SG_ P2D_BUCK_PHY_RX_Byte2_62 : 8|8@1+ (1,0) [0|255] ""  DCDC
 SG_ P2D_BUCK_PHY_RX_Byte3_62 : 16|8@1+ (1,0) [0|255] ""  DCDC
 SG_ P2D_BUCK_PHY_RX_Byte4_62 : 24|8@1+ (1,0) [0|255] ""  DCDC
 SG_ P2D_BUCK_PHY_RX_Byte5_62 : 32|8@1+ (1,0) [0|255] ""  DCDC
 SG_ P2D_BUCK_PHY_RX_Byte6_62 : 40|8@1+ (1,0) [0|255] ""  DCDC
 SG_ P2D_BUCK_PHY_RX_Byte7_62 : 48|8@1+ (1,0) [0|255] ""  DCDC
 SG_ P2D_BUCK_PHY_RX_Byte8_62 : 56|8@1+ (1,0) [0|255] ""  DCDC

BO_ 2149023615 P2D_BUCK_PHY_RX__63: 8 PC
 SG_ P2D_BUCK_PHY_RX_Byte1_63 : 0|8@1+ (1,0) [0|255] ""  DCDC
 SG_ P2D_BUCK_PHY_RX_Byte2_63 : 8|8@1+ (1,0) [0|255] ""  DCDC
 SG_ P2D_BUCK_PHY_RX_Byte3_63 : 16|8@1+ (1,0) [0|255] ""  DCDC
 SG_ P2D_BUCK_PHY_RX_Byte4_63 : 24|8@1+ (1,0) [0|255] ""  DCDC
 SG_ P2D_BUCK_PHY_RX_Byte5_63 : 32|8@1+ (1,0) [0|255] ""  DCDC
 SG_ P2D_BUCK_PHY_RX_Byte6_63 : 40|8@1+ (1,0) [0|255] ""  DCDC
 SG_ P2D_BUCK_PHY_RX_Byte7_63 : 48|8@1+ (1,0) [0|255] ""  DCDC
 SG_ P2D_BUCK_PHY_RX_Byte8_63 : 56|8@1+ (1,0) [0|255] ""  DCDC

BO_ 2149089089 P2D_BUCK_PHY_TX__01: 8 PC
 SG_ P2D_BUCK_PHY_TX_Byte1_01 : 0|8@1+ (1,0) [0|255] ""  DCDC
 SG_ P2D_BUCK_PHY_TX_Byte2_01 : 8|8@1+ (1,0) [0|255] ""  DCDC
 SG_ P2D_BUCK_PHY_TX_Byte3_01 : 16|8@1+ (1,0) [0|255] ""  DCDC
 SG_ P2D_BUCK_PHY_TX_Byte4_01 : 24|8@1+ (1,0) [0|255] ""  DCDC
 SG_ P2D_BUCK_PHY_TX_Byte5_01 : 32|8@1+ (1,0) [0|255] ""  DCDC
 SG_ P2D_BUCK_PHY_TX_Byte6_01 : 40|8@1+ (1,0) [0|255] ""  DCDC
 SG_ P2D_BUCK_PHY_TX_Byte7_01 : 48|8@1+ (1,0) [0|255] ""  DCDC
 SG_ P2D_BUCK_PHY_TX_Byte8_01 : 56|8@1+ (1,0) [0|255] ""  DCDC

BO_ 2149089090 P2D_BUCK_PHY_TX__02: 8 PC
 SG_ P2D_BUCK_PHY_TX_Byte1_02 : 0|8@1+ (1,0) [0|255] ""  DCDC
 SG_ P2D_BUCK_PHY_TX_Byte2_02 : 8|8@1+ (1,0) [0|255] ""  DCDC
 SG_ P2D_BUCK_PHY_TX_Byte3_02 : 16|8@1+ (1,0) [0|255] ""  DCDC
 SG_ P2D_BUCK_PHY_TX_Byte4_02 : 24|8@1+ (1,0) [0|255] ""  DCDC
 SG_ P2D_BUCK_PHY_TX_Byte5_02 : 32|8@1+ (1,0) [0|255] ""  DCDC
 SG_ P2D_BUCK_PHY_TX_Byte6_02 : 40|8@1+ (1,0) [0|255] ""  DCDC
 SG_ P2D_BUCK_PHY_TX_Byte7_02 : 48|8@1+ (1,0) [0|255] ""  DCDC
 SG_ P2D_BUCK_PHY_TX_Byte8_02 : 56|8@1+ (1,0) [0|255] ""  DCDC

BO_ 2149089091 P2D_BUCK_PHY_TX__03: 8 PC
 SG_ P2D_BUCK_PHY_TX_Byte1_03 : 0|8@1+ (1,0) [0|255] ""  DCDC
 SG_ P2D_BUCK_PHY_TX_Byte2_03 : 8|8@1+ (1,0) [0|255] ""  DCDC
 SG_ P2D_BUCK_PHY_TX_Byte3_03 : 16|8@1+ (1,0) [0|255] ""  DCDC
 SG_ P2D_BUCK_PHY_TX_Byte4_03 : 24|8@1+ (1,0) [0|255] ""  DCDC
 SG_ P2D_BUCK_PHY_TX_Byte5_03 : 32|8@1+ (1,0) [0|255] ""  DCDC
 SG_ P2D_BUCK_PHY_TX_Byte6_03 : 40|8@1+ (1,0) [0|255] ""  DCDC
 SG_ P2D_BUCK_PHY_TX_Byte7_03 : 48|8@1+ (1,0) [0|255] ""  DCDC
 SG_ P2D_BUCK_PHY_TX_Byte8_03 : 56|8@1+ (1,0) [0|255] ""  DCDC

BO_ 2149089092 P2D_BUCK_PHY_TX__04: 8 PC
 SG_ P2D_BUCK_PHY_TX_Byte1_04 : 0|8@1+ (1,0) [0|255] ""  DCDC
 SG_ P2D_BUCK_PHY_TX_Byte2_04 : 8|8@1+ (1,0) [0|255] ""  DCDC
 SG_ P2D_BUCK_PHY_TX_Byte3_04 : 16|8@1+ (1,0) [0|255] ""  DCDC
 SG_ P2D_BUCK_PHY_TX_Byte4_04 : 24|8@1+ (1,0) [0|255] ""  DCDC
 SG_ P2D_BUCK_PHY_TX_Byte5_04 : 32|8@1+ (1,0) [0|255] ""  DCDC
 SG_ P2D_BUCK_PHY_TX_Byte6_04 : 40|8@1+ (1,0) [0|255] ""  DCDC
 SG_ P2D_BUCK_PHY_TX_Byte7_04 : 48|8@1+ (1,0) [0|255] ""  DCDC
 SG_ P2D_BUCK_PHY_TX_Byte8_04 : 56|8@1+ (1,0) [0|255] ""  DCDC

BO_ 2149089093 P2D_BUCK_PHY_TX__05: 8 PC
 SG_ P2D_BUCK_PHY_TX_Byte1_05 : 0|8@1+ (1,0) [0|255] ""  DCDC
 SG_ P2D_BUCK_PHY_TX_Byte2_05 : 8|8@1+ (1,0) [0|255] ""  DCDC
 SG_ P2D_BUCK_PHY_TX_Byte3_05 : 16|8@1+ (1,0) [0|255] ""  DCDC
 SG_ P2D_BUCK_PHY_TX_Byte4_05 : 24|8@1+ (1,0) [0|255] ""  DCDC
 SG_ P2D_BUCK_PHY_TX_Byte5_05 : 32|8@1+ (1,0) [0|255] ""  DCDC
 SG_ P2D_BUCK_PHY_TX_Byte6_05 : 40|8@1+ (1,0) [0|255] ""  DCDC
 SG_ P2D_BUCK_PHY_TX_Byte7_05 : 48|8@1+ (1,0) [0|255] ""  DCDC
 SG_ P2D_BUCK_PHY_TX_Byte8_05 : 56|8@1+ (1,0) [0|255] ""  DCDC

BO_ 2149089094 P2D_BUCK_PHY_TX__06: 8 PC
 SG_ P2D_BUCK_PHY_TX_Byte1_06 : 0|8@1+ (1,0) [0|255] ""  DCDC
 SG_ P2D_BUCK_PHY_TX_Byte2_06 : 8|8@1+ (1,0) [0|255] ""  DCDC
 SG_ P2D_BUCK_PHY_TX_Byte3_06 : 16|8@1+ (1,0) [0|255] ""  DCDC
 SG_ P2D_BUCK_PHY_TX_Byte4_06 : 24|8@1+ (1,0) [0|255] ""  DCDC
 SG_ P2D_BUCK_PHY_TX_Byte5_06 : 32|8@1+ (1,0) [0|255] ""  DCDC
 SG_ P2D_BUCK_PHY_TX_Byte6_06 : 40|8@1+ (1,0) [0|255] ""  DCDC
 SG_ P2D_BUCK_PHY_TX_Byte7_06 : 48|8@1+ (1,0) [0|255] ""  DCDC
 SG_ P2D_BUCK_PHY_TX_Byte8_06 : 56|8@1+ (1,0) [0|255] ""  DCDC

BO_ 2149089095 P2D_BUCK_PHY_TX__07: 8 PC
 SG_ P2D_BUCK_PHY_TX_Byte1_07 : 0|8@1+ (1,0) [0|255] ""  DCDC
 SG_ P2D_BUCK_PHY_TX_Byte2_07 : 8|8@1+ (1,0) [0|255] ""  DCDC
 SG_ P2D_BUCK_PHY_TX_Byte3_07 : 16|8@1+ (1,0) [0|255] ""  DCDC
 SG_ P2D_BUCK_PHY_TX_Byte4_07 : 24|8@1+ (1,0) [0|255] ""  DCDC
 SG_ P2D_BUCK_PHY_TX_Byte5_07 : 32|8@1+ (1,0) [0|255] ""  DCDC
 SG_ P2D_BUCK_PHY_TX_Byte6_07 : 40|8@1+ (1,0) [0|255] ""  DCDC
 SG_ P2D_BUCK_PHY_TX_Byte7_07 : 48|8@1+ (1,0) [0|255] ""  DCDC
 SG_ P2D_BUCK_PHY_TX_Byte8_07 : 56|8@1+ (1,0) [0|255] ""  DCDC

BO_ 2149089096 P2D_BUCK_PHY_TX__08: 8 PC
 SG_ P2D_BUCK_PHY_TX_Byte1_08 : 0|8@1+ (1,0) [0|255] ""  DCDC
 SG_ P2D_BUCK_PHY_TX_Byte2_08 : 8|8@1+ (1,0) [0|255] ""  DCDC
 SG_ P2D_BUCK_PHY_TX_Byte3_08 : 16|8@1+ (1,0) [0|255] ""  DCDC
 SG_ P2D_BUCK_PHY_TX_Byte4_08 : 24|8@1+ (1,0) [0|255] ""  DCDC
 SG_ P2D_BUCK_PHY_TX_Byte5_08 : 32|8@1+ (1,0) [0|255] ""  DCDC
 SG_ P2D_BUCK_PHY_TX_Byte6_08 : 40|8@1+ (1,0) [0|255] ""  DCDC
 SG_ P2D_BUCK_PHY_TX_Byte7_08 : 48|8@1+ (1,0) [0|255] ""  DCDC
 SG_ P2D_BUCK_PHY_TX_Byte8_08 : 56|8@1+ (1,0) [0|255] ""  DCDC

BO_ 2149089097 P2D_BUCK_PHY_TX__09: 8 PC
 SG_ P2D_BUCK_PHY_TX_Byte1_09 : 0|8@1+ (1,0) [0|255] ""  DCDC
 SG_ P2D_BUCK_PHY_TX_Byte2_09 : 8|8@1+ (1,0) [0|255] ""  DCDC
 SG_ P2D_BUCK_PHY_TX_Byte3_09 : 16|8@1+ (1,0) [0|255] ""  DCDC
 SG_ P2D_BUCK_PHY_TX_Byte4_09 : 24|8@1+ (1,0) [0|255] ""  DCDC
 SG_ P2D_BUCK_PHY_TX_Byte5_09 : 32|8@1+ (1,0) [0|255] ""  DCDC
 SG_ P2D_BUCK_PHY_TX_Byte6_09 : 40|8@1+ (1,0) [0|255] ""  DCDC
 SG_ P2D_BUCK_PHY_TX_Byte7_09 : 48|8@1+ (1,0) [0|255] ""  DCDC
 SG_ P2D_BUCK_PHY_TX_Byte8_09 : 56|8@1+ (1,0) [0|255] ""  DCDC

BO_ 2149089098 P2D_BUCK_PHY_TX__10: 8 PC
 SG_ P2D_BUCK_PHY_TX_Byte1_10 : 0|8@1+ (1,0) [0|255] ""  DCDC
 SG_ P2D_BUCK_PHY_TX_Byte2_10 : 8|8@1+ (1,0) [0|255] ""  DCDC
 SG_ P2D_BUCK_PHY_TX_Byte3_10 : 16|8@1+ (1,0) [0|255] ""  DCDC
 SG_ P2D_BUCK_PHY_TX_Byte4_10 : 24|8@1+ (1,0) [0|255] ""  DCDC
 SG_ P2D_BUCK_PHY_TX_Byte5_10 : 32|8@1+ (1,0) [0|255] ""  DCDC
 SG_ P2D_BUCK_PHY_TX_Byte6_10 : 40|8@1+ (1,0) [0|255] ""  DCDC
 SG_ P2D_BUCK_PHY_TX_Byte7_10 : 48|8@1+ (1,0) [0|255] ""  DCDC
 SG_ P2D_BUCK_PHY_TX_Byte8_10 : 56|8@1+ (1,0) [0|255] ""  DCDC

BO_ 2149089099 P2D_BUCK_PHY_TX__11: 8 PC
 SG_ P2D_BUCK_PHY_TX_Byte1_11 : 0|8@1+ (1,0) [0|255] ""  DCDC
 SG_ P2D_BUCK_PHY_TX_Byte2_11 : 8|8@1+ (1,0) [0|255] ""  DCDC
 SG_ P2D_BUCK_PHY_TX_Byte3_11 : 16|8@1+ (1,0) [0|255] ""  DCDC
 SG_ P2D_BUCK_PHY_TX_Byte4_11 : 24|8@1+ (1,0) [0|255] ""  DCDC
 SG_ P2D_BUCK_PHY_TX_Byte5_11 : 32|8@1+ (1,0) [0|255] ""  DCDC
 SG_ P2D_BUCK_PHY_TX_Byte6_11 : 40|8@1+ (1,0) [0|255] ""  DCDC
 SG_ P2D_BUCK_PHY_TX_Byte7_11 : 48|8@1+ (1,0) [0|255] ""  DCDC
 SG_ P2D_BUCK_PHY_TX_Byte8_11 : 56|8@1+ (1,0) [0|255] ""  DCDC

BO_ 2149089100 P2D_BUCK_PHY_TX__12: 8 PC
 SG_ P2D_BUCK_PHY_TX_Byte1_12 : 0|8@1+ (1,0) [0|255] ""  DCDC
 SG_ P2D_BUCK_PHY_TX_Byte2_12 : 8|8@1+ (1,0) [0|255] ""  DCDC
 SG_ P2D_BUCK_PHY_TX_Byte3_12 : 16|8@1+ (1,0) [0|255] ""  DCDC
 SG_ P2D_BUCK_PHY_TX_Byte4_12 : 24|8@1+ (1,0) [0|255] ""  DCDC
 SG_ P2D_BUCK_PHY_TX_Byte5_12 : 32|8@1+ (1,0) [0|255] ""  DCDC
 SG_ P2D_BUCK_PHY_TX_Byte6_12 : 40|8@1+ (1,0) [0|255] ""  DCDC
 SG_ P2D_BUCK_PHY_TX_Byte7_12 : 48|8@1+ (1,0) [0|255] ""  DCDC
 SG_ P2D_BUCK_PHY_TX_Byte8_12 : 56|8@1+ (1,0) [0|255] ""  DCDC

BO_ 2149089101 P2D_BUCK_PHY_TX__13: 8 PC
 SG_ P2D_BUCK_PHY_TX_Byte1_13 : 0|8@1+ (1,0) [0|255] ""  DCDC
 SG_ P2D_BUCK_PHY_TX_Byte2_13 : 8|8@1+ (1,0) [0|255] ""  DCDC
 SG_ P2D_BUCK_PHY_TX_Byte3_13 : 16|8@1+ (1,0) [0|255] ""  DCDC
 SG_ P2D_BUCK_PHY_TX_Byte4_13 : 24|8@1+ (1,0) [0|255] ""  DCDC
 SG_ P2D_BUCK_PHY_TX_Byte5_13 : 32|8@1+ (1,0) [0|255] ""  DCDC
 SG_ P2D_BUCK_PHY_TX_Byte6_13 : 40|8@1+ (1,0) [0|255] ""  DCDC
 SG_ P2D_BUCK_PHY_TX_Byte7_13 : 48|8@1+ (1,0) [0|255] ""  DCDC
 SG_ P2D_BUCK_PHY_TX_Byte8_13 : 56|8@1+ (1,0) [0|255] ""  DCDC

BO_ 2149089102 P2D_BUCK_PHY_TX__14: 8 PC
 SG_ P2D_BUCK_PHY_TX_Byte1_14 : 0|8@1+ (1,0) [0|255] ""  DCDC
 SG_ P2D_BUCK_PHY_TX_Byte2_14 : 8|8@1+ (1,0) [0|255] ""  DCDC
 SG_ P2D_BUCK_PHY_TX_Byte3_14 : 16|8@1+ (1,0) [0|255] ""  DCDC
 SG_ P2D_BUCK_PHY_TX_Byte4_14 : 24|8@1+ (1,0) [0|255] ""  DCDC
 SG_ P2D_BUCK_PHY_TX_Byte5_14 : 32|8@1+ (1,0) [0|255] ""  DCDC
 SG_ P2D_BUCK_PHY_TX_Byte6_14 : 40|8@1+ (1,0) [0|255] ""  DCDC
 SG_ P2D_BUCK_PHY_TX_Byte7_14 : 48|8@1+ (1,0) [0|255] ""  DCDC
 SG_ P2D_BUCK_PHY_TX_Byte8_14 : 56|8@1+ (1,0) [0|255] ""  DCDC

BO_ 2149089103 P2D_BUCK_PHY_TX__15: 8 PC
 SG_ P2D_BUCK_PHY_TX_Byte1_15 : 0|8@1+ (1,0) [0|255] ""  DCDC
 SG_ P2D_BUCK_PHY_TX_Byte2_15 : 8|8@1+ (1,0) [0|255] ""  DCDC
 SG_ P2D_BUCK_PHY_TX_Byte3_15 : 16|8@1+ (1,0) [0|255] ""  DCDC
 SG_ P2D_BUCK_PHY_TX_Byte4_15 : 24|8@1+ (1,0) [0|255] ""  DCDC
 SG_ P2D_BUCK_PHY_TX_Byte5_15 : 32|8@1+ (1,0) [0|255] ""  DCDC
 SG_ P2D_BUCK_PHY_TX_Byte6_15 : 40|8@1+ (1,0) [0|255] ""  DCDC
 SG_ P2D_BUCK_PHY_TX_Byte7_15 : 48|8@1+ (1,0) [0|255] ""  DCDC
 SG_ P2D_BUCK_PHY_TX_Byte8_15 : 56|8@1+ (1,0) [0|255] ""  DCDC

BO_ 2149089104 P2D_BUCK_PHY_TX__16: 8 PC
 SG_ P2D_BUCK_PHY_TX_Byte1_16 : 0|8@1+ (1,0) [0|255] ""  DCDC
 SG_ P2D_BUCK_PHY_TX_Byte2_16 : 8|8@1+ (1,0) [0|255] ""  DCDC
 SG_ P2D_BUCK_PHY_TX_Byte3_16 : 16|8@1+ (1,0) [0|255] ""  DCDC
 SG_ P2D_BUCK_PHY_TX_Byte4_16 : 24|8@1+ (1,0) [0|255] ""  DCDC
 SG_ P2D_BUCK_PHY_TX_Byte5_16 : 32|8@1+ (1,0) [0|255] ""  DCDC
 SG_ P2D_BUCK_PHY_TX_Byte6_16 : 40|8@1+ (1,0) [0|255] ""  DCDC
 SG_ P2D_BUCK_PHY_TX_Byte7_16 : 48|8@1+ (1,0) [0|255] ""  DCDC
 SG_ P2D_BUCK_PHY_TX_Byte8_16 : 56|8@1+ (1,0) [0|255] ""  DCDC

BO_ 2149089105 P2D_BUCK_PHY_TX__17: 8 PC
 SG_ P2D_BUCK_PHY_TX_Byte1_17 : 0|8@1+ (1,0) [0|255] ""  DCDC
 SG_ P2D_BUCK_PHY_TX_Byte2_17 : 8|8@1+ (1,0) [0|255] ""  DCDC
 SG_ P2D_BUCK_PHY_TX_Byte3_17 : 16|8@1+ (1,0) [0|255] ""  DCDC
 SG_ P2D_BUCK_PHY_TX_Byte4_17 : 24|8@1+ (1,0) [0|255] ""  DCDC
 SG_ P2D_BUCK_PHY_TX_Byte5_17 : 32|8@1+ (1,0) [0|255] ""  DCDC
 SG_ P2D_BUCK_PHY_TX_Byte6_17 : 40|8@1+ (1,0) [0|255] ""  DCDC
 SG_ P2D_BUCK_PHY_TX_Byte7_17 : 48|8@1+ (1,0) [0|255] ""  DCDC
 SG_ P2D_BUCK_PHY_TX_Byte8_17 : 56|8@1+ (1,0) [0|255] ""  DCDC

BO_ 2149089106 P2D_BUCK_PHY_TX__18: 8 PC
 SG_ P2D_BUCK_PHY_TX_Byte1_18 : 0|8@1+ (1,0) [0|255] ""  DCDC
 SG_ P2D_BUCK_PHY_TX_Byte2_18 : 8|8@1+ (1,0) [0|255] ""  DCDC
 SG_ P2D_BUCK_PHY_TX_Byte3_18 : 16|8@1+ (1,0) [0|255] ""  DCDC
 SG_ P2D_BUCK_PHY_TX_Byte4_18 : 24|8@1+ (1,0) [0|255] ""  DCDC
 SG_ P2D_BUCK_PHY_TX_Byte5_18 : 32|8@1+ (1,0) [0|255] ""  DCDC
 SG_ P2D_BUCK_PHY_TX_Byte6_18 : 40|8@1+ (1,0) [0|255] ""  DCDC
 SG_ P2D_BUCK_PHY_TX_Byte7_18 : 48|8@1+ (1,0) [0|255] ""  DCDC
 SG_ P2D_BUCK_PHY_TX_Byte8_18 : 56|8@1+ (1,0) [0|255] ""  DCDC

BO_ 2149089107 P2D_BUCK_PHY_TX__19: 8 PC
 SG_ P2D_BUCK_PHY_TX_Byte1_19 : 0|8@1+ (1,0) [0|255] ""  DCDC
 SG_ P2D_BUCK_PHY_TX_Byte2_19 : 8|8@1+ (1,0) [0|255] ""  DCDC
 SG_ P2D_BUCK_PHY_TX_Byte3_19 : 16|8@1+ (1,0) [0|255] ""  DCDC
 SG_ P2D_BUCK_PHY_TX_Byte4_19 : 24|8@1+ (1,0) [0|255] ""  DCDC
 SG_ P2D_BUCK_PHY_TX_Byte5_19 : 32|8@1+ (1,0) [0|255] ""  DCDC
 SG_ P2D_BUCK_PHY_TX_Byte6_19 : 40|8@1+ (1,0) [0|255] ""  DCDC
 SG_ P2D_BUCK_PHY_TX_Byte7_19 : 48|8@1+ (1,0) [0|255] ""  DCDC
 SG_ P2D_BUCK_PHY_TX_Byte8_19 : 56|8@1+ (1,0) [0|255] ""  DCDC

BO_ 2149089108 P2D_BUCK_PHY_TX__20: 8 PC
 SG_ P2D_BUCK_PHY_TX_Byte1_20 : 0|8@1+ (1,0) [0|255] ""  DCDC
 SG_ P2D_BUCK_PHY_TX_Byte2_20 : 8|8@1+ (1,0) [0|255] ""  DCDC
 SG_ P2D_BUCK_PHY_TX_Byte3_20 : 16|8@1+ (1,0) [0|255] ""  DCDC
 SG_ P2D_BUCK_PHY_TX_Byte4_20 : 24|8@1+ (1,0) [0|255] ""  DCDC
 SG_ P2D_BUCK_PHY_TX_Byte5_20 : 32|8@1+ (1,0) [0|255] ""  DCDC
 SG_ P2D_BUCK_PHY_TX_Byte6_20 : 40|8@1+ (1,0) [0|255] ""  DCDC
 SG_ P2D_BUCK_PHY_TX_Byte7_20 : 48|8@1+ (1,0) [0|255] ""  DCDC
 SG_ P2D_BUCK_PHY_TX_Byte8_20 : 56|8@1+ (1,0) [0|255] ""  DCDC

BO_ 2149089109 P2D_BUCK_PHY_TX__21: 8 PC
 SG_ P2D_BUCK_PHY_TX_Byte1_21 : 0|8@1+ (1,0) [0|255] ""  DCDC
 SG_ P2D_BUCK_PHY_TX_Byte2_21 : 8|8@1+ (1,0) [0|255] ""  DCDC
 SG_ P2D_BUCK_PHY_TX_Byte3_21 : 16|8@1+ (1,0) [0|255] ""  DCDC
 SG_ P2D_BUCK_PHY_TX_Byte4_21 : 24|8@1+ (1,0) [0|255] ""  DCDC
 SG_ P2D_BUCK_PHY_TX_Byte5_21 : 32|8@1+ (1,0) [0|255] ""  DCDC
 SG_ P2D_BUCK_PHY_TX_Byte6_21 : 40|8@1+ (1,0) [0|255] ""  DCDC
 SG_ P2D_BUCK_PHY_TX_Byte7_21 : 48|8@1+ (1,0) [0|255] ""  DCDC
 SG_ P2D_BUCK_PHY_TX_Byte8_21 : 56|8@1+ (1,0) [0|255] ""  DCDC

BO_ 2149089110 P2D_BUCK_PHY_TX__22: 8 PC
 SG_ P2D_BUCK_PHY_TX_Byte1_22 : 0|8@1+ (1,0) [0|255] ""  DCDC
 SG_ P2D_BUCK_PHY_TX_Byte2_22 : 8|8@1+ (1,0) [0|255] ""  DCDC
 SG_ P2D_BUCK_PHY_TX_Byte3_22 : 16|8@1+ (1,0) [0|255] ""  DCDC
 SG_ P2D_BUCK_PHY_TX_Byte4_22 : 24|8@1+ (1,0) [0|255] ""  DCDC
 SG_ P2D_BUCK_PHY_TX_Byte5_22 : 32|8@1+ (1,0) [0|255] ""  DCDC
 SG_ P2D_BUCK_PHY_TX_Byte6_22 : 40|8@1+ (1,0) [0|255] ""  DCDC
 SG_ P2D_BUCK_PHY_TX_Byte7_22 : 48|8@1+ (1,0) [0|255] ""  DCDC
 SG_ P2D_BUCK_PHY_TX_Byte8_22 : 56|8@1+ (1,0) [0|255] ""  DCDC

BO_ 2149089111 P2D_BUCK_PHY_TX__23: 8 PC
 SG_ P2D_BUCK_PHY_TX_Byte1_23 : 0|8@1+ (1,0) [0|255] ""  DCDC
 SG_ P2D_BUCK_PHY_TX_Byte2_23 : 8|8@1+ (1,0) [0|255] ""  DCDC
 SG_ P2D_BUCK_PHY_TX_Byte3_23 : 16|8@1+ (1,0) [0|255] ""  DCDC
 SG_ P2D_BUCK_PHY_TX_Byte4_23 : 24|8@1+ (1,0) [0|255] ""  DCDC
 SG_ P2D_BUCK_PHY_TX_Byte5_23 : 32|8@1+ (1,0) [0|255] ""  DCDC
 SG_ P2D_BUCK_PHY_TX_Byte6_23 : 40|8@1+ (1,0) [0|255] ""  DCDC
 SG_ P2D_BUCK_PHY_TX_Byte7_23 : 48|8@1+ (1,0) [0|255] ""  DCDC
 SG_ P2D_BUCK_PHY_TX_Byte8_23 : 56|8@1+ (1,0) [0|255] ""  DCDC

BO_ 2149089112 P2D_BUCK_PHY_TX__24: 8 PC
 SG_ P2D_BUCK_PHY_TX_Byte1_24 : 0|8@1+ (1,0) [0|255] ""  DCDC
 SG_ P2D_BUCK_PHY_TX_Byte2_24 : 8|8@1+ (1,0) [0|255] ""  DCDC
 SG_ P2D_BUCK_PHY_TX_Byte3_24 : 16|8@1+ (1,0) [0|255] ""  DCDC
 SG_ P2D_BUCK_PHY_TX_Byte4_24 : 24|8@1+ (1,0) [0|255] ""  DCDC
 SG_ P2D_BUCK_PHY_TX_Byte5_24 : 32|8@1+ (1,0) [0|255] ""  DCDC
 SG_ P2D_BUCK_PHY_TX_Byte6_24 : 40|8@1+ (1,0) [0|255] ""  DCDC
 SG_ P2D_BUCK_PHY_TX_Byte7_24 : 48|8@1+ (1,0) [0|255] ""  DCDC
 SG_ P2D_BUCK_PHY_TX_Byte8_24 : 56|8@1+ (1,0) [0|255] ""  DCDC

BO_ 2149089113 P2D_BUCK_PHY_TX__25: 8 PC
 SG_ P2D_BUCK_PHY_TX_Byte1_25 : 0|8@1+ (1,0) [0|255] ""  DCDC
 SG_ P2D_BUCK_PHY_TX_Byte2_25 : 8|8@1+ (1,0) [0|255] ""  DCDC
 SG_ P2D_BUCK_PHY_TX_Byte3_25 : 16|8@1+ (1,0) [0|255] ""  DCDC
 SG_ P2D_BUCK_PHY_TX_Byte4_25 : 24|8@1+ (1,0) [0|255] ""  DCDC
 SG_ P2D_BUCK_PHY_TX_Byte5_25 : 32|8@1+ (1,0) [0|255] ""  DCDC
 SG_ P2D_BUCK_PHY_TX_Byte6_25 : 40|8@1+ (1,0) [0|255] ""  DCDC
 SG_ P2D_BUCK_PHY_TX_Byte7_25 : 48|8@1+ (1,0) [0|255] ""  DCDC
 SG_ P2D_BUCK_PHY_TX_Byte8_25 : 56|8@1+ (1,0) [0|255] ""  DCDC

BO_ 2149089114 P2D_BUCK_PHY_TX__26: 8 PC
 SG_ P2D_BUCK_PHY_TX_Byte1_26 : 0|8@1+ (1,0) [0|255] ""  DCDC
 SG_ P2D_BUCK_PHY_TX_Byte2_26 : 8|8@1+ (1,0) [0|255] ""  DCDC
 SG_ P2D_BUCK_PHY_TX_Byte3_26 : 16|8@1+ (1,0) [0|255] ""  DCDC
 SG_ P2D_BUCK_PHY_TX_Byte4_26 : 24|8@1+ (1,0) [0|255] ""  DCDC
 SG_ P2D_BUCK_PHY_TX_Byte5_26 : 32|8@1+ (1,0) [0|255] ""  DCDC
 SG_ P2D_BUCK_PHY_TX_Byte6_26 : 40|8@1+ (1,0) [0|255] ""  DCDC
 SG_ P2D_BUCK_PHY_TX_Byte7_26 : 48|8@1+ (1,0) [0|255] ""  DCDC
 SG_ P2D_BUCK_PHY_TX_Byte8_26 : 56|8@1+ (1,0) [0|255] ""  DCDC

BO_ 2149089115 P2D_BUCK_PHY_TX__27: 8 PC
 SG_ P2D_BUCK_PHY_TX_Byte1_27 : 0|8@1+ (1,0) [0|255] ""  DCDC
 SG_ P2D_BUCK_PHY_TX_Byte2_27 : 8|8@1+ (1,0) [0|255] ""  DCDC
 SG_ P2D_BUCK_PHY_TX_Byte3_27 : 16|8@1+ (1,0) [0|255] ""  DCDC
 SG_ P2D_BUCK_PHY_TX_Byte4_27 : 24|8@1+ (1,0) [0|255] ""  DCDC
 SG_ P2D_BUCK_PHY_TX_Byte5_27 : 32|8@1+ (1,0) [0|255] ""  DCDC
 SG_ P2D_BUCK_PHY_TX_Byte6_27 : 40|8@1+ (1,0) [0|255] ""  DCDC
 SG_ P2D_BUCK_PHY_TX_Byte7_27 : 48|8@1+ (1,0) [0|255] ""  DCDC
 SG_ P2D_BUCK_PHY_TX_Byte8_27 : 56|8@1+ (1,0) [0|255] ""  DCDC

BO_ 2149089116 P2D_BUCK_PHY_TX__28: 8 PC
 SG_ P2D_BUCK_PHY_TX_Byte1_28 : 0|8@1+ (1,0) [0|255] ""  DCDC
 SG_ P2D_BUCK_PHY_TX_Byte2_28 : 8|8@1+ (1,0) [0|255] ""  DCDC
 SG_ P2D_BUCK_PHY_TX_Byte3_28 : 16|8@1+ (1,0) [0|255] ""  DCDC
 SG_ P2D_BUCK_PHY_TX_Byte4_28 : 24|8@1+ (1,0) [0|255] ""  DCDC
 SG_ P2D_BUCK_PHY_TX_Byte5_28 : 32|8@1+ (1,0) [0|255] ""  DCDC
 SG_ P2D_BUCK_PHY_TX_Byte6_28 : 40|8@1+ (1,0) [0|255] ""  DCDC
 SG_ P2D_BUCK_PHY_TX_Byte7_28 : 48|8@1+ (1,0) [0|255] ""  DCDC
 SG_ P2D_BUCK_PHY_TX_Byte8_28 : 56|8@1+ (1,0) [0|255] ""  DCDC

BO_ 2149089117 P2D_BUCK_PHY_TX__29: 8 PC
 SG_ P2D_BUCK_PHY_TX_Byte1_29 : 0|8@1+ (1,0) [0|255] ""  DCDC
 SG_ P2D_BUCK_PHY_TX_Byte2_29 : 8|8@1+ (1,0) [0|255] ""  DCDC
 SG_ P2D_BUCK_PHY_TX_Byte3_29 : 16|8@1+ (1,0) [0|255] ""  DCDC
 SG_ P2D_BUCK_PHY_TX_Byte4_29 : 24|8@1+ (1,0) [0|255] ""  DCDC
 SG_ P2D_BUCK_PHY_TX_Byte5_29 : 32|8@1+ (1,0) [0|255] ""  DCDC
 SG_ P2D_BUCK_PHY_TX_Byte6_29 : 40|8@1+ (1,0) [0|255] ""  DCDC
 SG_ P2D_BUCK_PHY_TX_Byte7_29 : 48|8@1+ (1,0) [0|255] ""  DCDC
 SG_ P2D_BUCK_PHY_TX_Byte8_29 : 56|8@1+ (1,0) [0|255] ""  DCDC

BO_ 2149089118 P2D_BUCK_PHY_TX__30: 8 PC
 SG_ P2D_BUCK_PHY_TX_Byte1_30 : 0|8@1+ (1,0) [0|255] ""  DCDC
 SG_ P2D_BUCK_PHY_TX_Byte2_30 : 8|8@1+ (1,0) [0|255] ""  DCDC
 SG_ P2D_BUCK_PHY_TX_Byte3_30 : 16|8@1+ (1,0) [0|255] ""  DCDC
 SG_ P2D_BUCK_PHY_TX_Byte4_30 : 24|8@1+ (1,0) [0|255] ""  DCDC
 SG_ P2D_BUCK_PHY_TX_Byte5_30 : 32|8@1+ (1,0) [0|255] ""  DCDC
 SG_ P2D_BUCK_PHY_TX_Byte6_30 : 40|8@1+ (1,0) [0|255] ""  DCDC
 SG_ P2D_BUCK_PHY_TX_Byte7_30 : 48|8@1+ (1,0) [0|255] ""  DCDC
 SG_ P2D_BUCK_PHY_TX_Byte8_30 : 56|8@1+ (1,0) [0|255] ""  DCDC

BO_ 2149089119 P2D_BUCK_PHY_TX__31: 8 PC
 SG_ P2D_BUCK_PHY_TX_Byte1_31 : 0|8@1+ (1,0) [0|255] ""  DCDC
 SG_ P2D_BUCK_PHY_TX_Byte2_31 : 8|8@1+ (1,0) [0|255] ""  DCDC
 SG_ P2D_BUCK_PHY_TX_Byte3_31 : 16|8@1+ (1,0) [0|255] ""  DCDC
 SG_ P2D_BUCK_PHY_TX_Byte4_31 : 24|8@1+ (1,0) [0|255] ""  DCDC
 SG_ P2D_BUCK_PHY_TX_Byte5_31 : 32|8@1+ (1,0) [0|255] ""  DCDC
 SG_ P2D_BUCK_PHY_TX_Byte6_31 : 40|8@1+ (1,0) [0|255] ""  DCDC
 SG_ P2D_BUCK_PHY_TX_Byte7_31 : 48|8@1+ (1,0) [0|255] ""  DCDC
 SG_ P2D_BUCK_PHY_TX_Byte8_31 : 56|8@1+ (1,0) [0|255] ""  DCDC

BO_ 2149089120 P2D_BUCK_PHY_TX__32: 8 PC
 SG_ P2D_BUCK_PHY_TX_Byte1_32 : 0|8@1+ (1,0) [0|255] ""  DCDC
 SG_ P2D_BUCK_PHY_TX_Byte2_32 : 8|8@1+ (1,0) [0|255] ""  DCDC
 SG_ P2D_BUCK_PHY_TX_Byte3_32 : 16|8@1+ (1,0) [0|255] ""  DCDC
 SG_ P2D_BUCK_PHY_TX_Byte4_32 : 24|8@1+ (1,0) [0|255] ""  DCDC
 SG_ P2D_BUCK_PHY_TX_Byte5_32 : 32|8@1+ (1,0) [0|255] ""  DCDC
 SG_ P2D_BUCK_PHY_TX_Byte6_32 : 40|8@1+ (1,0) [0|255] ""  DCDC
 SG_ P2D_BUCK_PHY_TX_Byte7_32 : 48|8@1+ (1,0) [0|255] ""  DCDC
 SG_ P2D_BUCK_PHY_TX_Byte8_32 : 56|8@1+ (1,0) [0|255] ""  DCDC

CM_ SG_ 2148892521 M2D_CMD2_CRC_41 "CRC校验";
CM_ SG_ 2148892521 M2D_IDX_CMD_Type_41 "MBMU发送给DCDC的自动编码命令类型";
CM_ SG_ 2148892521 M2D_IDX_DCDC_Index_41 "MBMU发送给DCDC的DCDC的编码地址";
CM_ SG_ 2148892521 M2D_IDX_DCDC_Matchingcode_41 "MBMU发送给DCDC的DCDC的匹配码";
CM_ SG_ 2148892521 M2D_IDX_Reserved_41 "预留";
CM_ SG_ 2148892522 M2D_CMD2_CRC_42 "CRC校验";
CM_ SG_ 2148892522 M2D_IDX_CMD_Type_42 "MBMU发送给DCDC的自动编码命令类型";
CM_ SG_ 2148892522 M2D_IDX_DCDC_Index_42 "MBMU发送给DCDC的DCDC的编码地址";
CM_ SG_ 2148892522 M2D_IDX_DCDC_Matchingcode_42 "MBMU发送给DCDC的DCDC的匹配码";
CM_ SG_ 2148892522 M2D_IDX_Reserved_42 "预留";
CM_ SG_ 2148892523 M2D_CMD2_CRC_43 "CRC校验";
CM_ SG_ 2148892523 M2D_IDX_CMD_Type_43 "MBMU发送给DCDC的自动编码命令类型";
CM_ SG_ 2148892523 M2D_IDX_DCDC_Index_43 "MBMU发送给DCDC的DCDC的编码地址";
CM_ SG_ 2148892523 M2D_IDX_DCDC_Matchingcode_43 "MBMU发送给DCDC的DCDC的匹配码";
CM_ SG_ 2148892523 M2D_IDX_Reserved_43 "预留";
CM_ SG_ 2148892524 M2D_CMD2_CRC_44 "CRC校验";
CM_ SG_ 2148892524 M2D_IDX_CMD_Type_44 "MBMU发送给DCDC的自动编码命令类型";
CM_ SG_ 2148892524 M2D_IDX_DCDC_Index_44 "MBMU发送给DCDC的DCDC的编码地址";
CM_ SG_ 2148892524 M2D_IDX_DCDC_Matchingcode_44 "MBMU发送给DCDC的DCDC的匹配码";
CM_ SG_ 2148892524 M2D_IDX_Reserved_44 "预留";
CM_ SG_ 2148892525 M2D_CMD2_CRC_45 "CRC校验";
CM_ SG_ 2148892525 M2D_IDX_CMD_Type_45 "MBMU发送给DCDC的自动编码命令类型";
CM_ SG_ 2148892525 M2D_IDX_DCDC_Index_45 "MBMU发送给DCDC的DCDC的编码地址";
CM_ SG_ 2148892525 M2D_IDX_DCDC_Matchingcode_45 "MBMU发送给DCDC的DCDC的匹配码";
CM_ SG_ 2148892525 M2D_IDX_Reserved_45 "预留";
CM_ SG_ 2148892526 M2D_CMD2_CRC_46 "CRC校验";
CM_ SG_ 2148892526 M2D_IDX_CMD_Type_46 "MBMU发送给DCDC的自动编码命令类型";
CM_ SG_ 2148892526 M2D_IDX_DCDC_Index_46 "MBMU发送给DCDC的DCDC的编码地址";
CM_ SG_ 2148892526 M2D_IDX_DCDC_Matchingcode_46 "MBMU发送给DCDC的DCDC的匹配码";
CM_ SG_ 2148892526 M2D_IDX_Reserved_46 "预留";
CM_ SG_ 2148892527 M2D_CMD2_CRC_47 "CRC校验";
CM_ SG_ 2148892527 M2D_IDX_CMD_Type_47 "MBMU发送给DCDC的自动编码命令类型";
CM_ SG_ 2148892527 M2D_IDX_DCDC_Index_47 "MBMU发送给DCDC的DCDC的编码地址";
CM_ SG_ 2148892527 M2D_IDX_DCDC_Matchingcode_47 "MBMU发送给DCDC的DCDC的匹配码";
CM_ SG_ 2148892527 M2D_IDX_Reserved_47 "预留";
CM_ SG_ 2148892528 M2D_CMD2_CRC_48 "CRC校验";
CM_ SG_ 2148892528 M2D_IDX_CMD_Type_48 "MBMU发送给DCDC的自动编码命令类型";
CM_ SG_ 2148892528 M2D_IDX_DCDC_Index_48 "MBMU发送给DCDC的DCDC的编码地址";
CM_ SG_ 2148892528 M2D_IDX_DCDC_Matchingcode_48 "MBMU发送给DCDC的DCDC的匹配码";
CM_ SG_ 2148892528 M2D_IDX_Reserved_48 "预留";
CM_ SG_ 2148892529 M2D_CMD2_CRC_49 "CRC校验";
CM_ SG_ 2148892529 M2D_IDX_CMD_Type_49 "MBMU发送给DCDC的自动编码命令类型";
CM_ SG_ 2148892529 M2D_IDX_DCDC_Index_49 "MBMU发送给DCDC的DCDC的编码地址";
CM_ SG_ 2148892529 M2D_IDX_DCDC_Matchingcode_49 "MBMU发送给DCDC的DCDC的匹配码";
CM_ SG_ 2148892529 M2D_IDX_Reserved_49 "预留";
CM_ SG_ 2148892530 M2D_CMD2_CRC_50 "CRC校验";
CM_ SG_ 2148892530 M2D_IDX_CMD_Type_50 "MBMU发送给DCDC的自动编码命令类型";
CM_ SG_ 2148892530 M2D_IDX_DCDC_Index_50 "MBMU发送给DCDC的DCDC的编码地址";
CM_ SG_ 2148892530 M2D_IDX_DCDC_Matchingcode_50 "MBMU发送给DCDC的DCDC的匹配码";
CM_ SG_ 2148892530 M2D_IDX_Reserved_50 "预留";
CM_ SG_ 2148892531 M2D_CMD2_CRC_51 "CRC校验";
CM_ SG_ 2148892531 M2D_IDX_CMD_Type_51 "MBMU发送给DCDC的自动编码命令类型";
CM_ SG_ 2148892531 M2D_IDX_DCDC_Index_51 "MBMU发送给DCDC的DCDC的编码地址";
CM_ SG_ 2148892531 M2D_IDX_DCDC_Matchingcode_51 "MBMU发送给DCDC的DCDC的匹配码";
CM_ SG_ 2148892531 M2D_IDX_Reserved_51 "预留";
CM_ SG_ 2148892532 M2D_CMD2_CRC_52 "CRC校验";
CM_ SG_ 2148892532 M2D_IDX_CMD_Type_52 "MBMU发送给DCDC的自动编码命令类型";
CM_ SG_ 2148892532 M2D_IDX_DCDC_Index_52 "MBMU发送给DCDC的DCDC的编码地址";
CM_ SG_ 2148892532 M2D_IDX_DCDC_Matchingcode_52 "MBMU发送给DCDC的DCDC的匹配码";
CM_ SG_ 2148892532 M2D_IDX_Reserved_52 "预留";
CM_ SG_ 2148892533 M2D_CMD2_CRC_53 "CRC校验";
CM_ SG_ 2148892533 M2D_IDX_CMD_Type_53 "MBMU发送给DCDC的自动编码命令类型";
CM_ SG_ 2148892533 M2D_IDX_DCDC_Index_53 "MBMU发送给DCDC的DCDC的编码地址";
CM_ SG_ 2148892533 M2D_IDX_DCDC_Matchingcode_53 "MBMU发送给DCDC的DCDC的匹配码";
CM_ SG_ 2148892533 M2D_IDX_Reserved_53 "预留";
CM_ SG_ 2148892534 M2D_CMD2_CRC_54 "CRC校验";
CM_ SG_ 2148892534 M2D_IDX_CMD_Type_54 "MBMU发送给DCDC的自动编码命令类型";
CM_ SG_ 2148892534 M2D_IDX_DCDC_Index_54 "MBMU发送给DCDC的DCDC的编码地址";
CM_ SG_ 2148892534 M2D_IDX_DCDC_Matchingcode_54 "MBMU发送给DCDC的DCDC的匹配码";
CM_ SG_ 2148892534 M2D_IDX_Reserved_54 "预留";
CM_ SG_ 2148892535 M2D_CMD2_CRC_55 "CRC校验";
CM_ SG_ 2148892535 M2D_IDX_CMD_Type_55 "MBMU发送给DCDC的自动编码命令类型";
CM_ SG_ 2148892535 M2D_IDX_DCDC_Index_55 "MBMU发送给DCDC的DCDC的编码地址";
CM_ SG_ 2148892535 M2D_IDX_DCDC_Matchingcode_55 "MBMU发送给DCDC的DCDC的匹配码";
CM_ SG_ 2148892535 M2D_IDX_Reserved_55 "预留";
CM_ SG_ 2148892536 M2D_CMD2_CRC_56 "CRC校验";
CM_ SG_ 2148892536 M2D_IDX_CMD_Type_56 "MBMU发送给DCDC的自动编码命令类型";
CM_ SG_ 2148892536 M2D_IDX_DCDC_Index_56 "MBMU发送给DCDC的DCDC的编码地址";
CM_ SG_ 2148892536 M2D_IDX_DCDC_Matchingcode_56 "MBMU发送给DCDC的DCDC的匹配码";
CM_ SG_ 2148892536 M2D_IDX_Reserved_56 "预留";
CM_ SG_ 2148892537 M2D_CMD2_CRC_57 "CRC校验";
CM_ SG_ 2148892537 M2D_IDX_CMD_Type_57 "MBMU发送给DCDC的自动编码命令类型";
CM_ SG_ 2148892537 M2D_IDX_DCDC_Index_57 "MBMU发送给DCDC的DCDC的编码地址";
CM_ SG_ 2148892537 M2D_IDX_DCDC_Matchingcode_57 "MBMU发送给DCDC的DCDC的匹配码";
CM_ SG_ 2148892537 M2D_IDX_Reserved_57 "预留";
CM_ SG_ 2148892538 M2D_CMD2_CRC_58 "CRC校验";
CM_ SG_ 2148892538 M2D_IDX_CMD_Type_58 "MBMU发送给DCDC的自动编码命令类型";
CM_ SG_ 2148892538 M2D_IDX_DCDC_Index_58 "MBMU发送给DCDC的DCDC的编码地址";
CM_ SG_ 2148892538 M2D_IDX_DCDC_Matchingcode_58 "MBMU发送给DCDC的DCDC的匹配码";
CM_ SG_ 2148892538 M2D_IDX_Reserved_58 "预留";
CM_ SG_ 2148892539 M2D_CMD2_CRC_59 "CRC校验";
CM_ SG_ 2148892539 M2D_IDX_CMD_Type_59 "MBMU发送给DCDC的自动编码命令类型";
CM_ SG_ 2148892539 M2D_IDX_DCDC_Index_59 "MBMU发送给DCDC的DCDC的编码地址";
CM_ SG_ 2148892539 M2D_IDX_DCDC_Matchingcode_59 "MBMU发送给DCDC的DCDC的匹配码";
CM_ SG_ 2148892539 M2D_IDX_Reserved_59 "预留";
CM_ SG_ 2148892540 M2D_CMD2_CRC_60 "CRC校验";
CM_ SG_ 2148892540 M2D_IDX_CMD_Type_60 "MBMU发送给DCDC的自动编码命令类型";
CM_ SG_ 2148892540 M2D_IDX_DCDC_Index_60 "MBMU发送给DCDC的DCDC的编码地址";
CM_ SG_ 2148892540 M2D_IDX_DCDC_Matchingcode_60 "MBMU发送给DCDC的DCDC的匹配码";
CM_ SG_ 2148892540 M2D_IDX_Reserved_60 "预留";
CM_ SG_ 2148892541 M2D_CMD2_CRC_61 "CRC校验";
CM_ SG_ 2148892541 M2D_IDX_CMD_Type_61 "MBMU发送给DCDC的自动编码命令类型";
CM_ SG_ 2148892541 M2D_IDX_DCDC_Index_61 "MBMU发送给DCDC的DCDC的编码地址";
CM_ SG_ 2148892541 M2D_IDX_DCDC_Matchingcode_61 "MBMU发送给DCDC的DCDC的匹配码";
CM_ SG_ 2148892541 M2D_IDX_Reserved_61 "预留";
CM_ SG_ 2148892542 M2D_CMD2_CRC_62 "CRC校验";
CM_ SG_ 2148892542 M2D_IDX_CMD_Type_62 "MBMU发送给DCDC的自动编码命令类型";
CM_ SG_ 2148892542 M2D_IDX_DCDC_Index_62 "MBMU发送给DCDC的DCDC的编码地址";
CM_ SG_ 2148892542 M2D_IDX_DCDC_Matchingcode_62 "MBMU发送给DCDC的DCDC的匹配码";
CM_ SG_ 2148892542 M2D_IDX_Reserved_62 "预留";
CM_ SG_ 2148892543 M2D_CMD2_CRC_63 "CRC校验";
CM_ SG_ 2148892543 M2D_IDX_CMD_Type_63 "MBMU发送给DCDC的自动编码命令类型";
CM_ SG_ 2148892543 M2D_IDX_DCDC_Index_63 "MBMU发送给DCDC的DCDC的编码地址";
CM_ SG_ 2148892543 M2D_IDX_DCDC_Matchingcode_63 "MBMU发送给DCDC的DCDC的匹配码";
CM_ SG_ 2148892543 M2D_IDX_Reserved_63 "预留";
CM_ SG_ 2149034734 P2D_Read_DCDC_Ver_01 "PC读取哪一个DCDC版本号";
CM_ SG_ 2149034734 P2D_Read_DCDCSW_Ver_01 "读取DCDC软件版本号指令";
CM_ SG_ 2149034734 P2D_Read_DCDCBoot_Ver_01 "读取DCDC boot版本号指令";
CM_ SG_ 2149034734 P2D_Read_DCDCHW_Ver_01 "读取DCDC 硬件版本号指令";
CM_ SG_ 2149034734 P2D_Read_DCDC_Barcode_01 "读取DCDC barcode指令";
CM_ SG_ 2149034734 P2D_RQ_Read_Detail_Data_01 "PC请求读取DCDC的详细信息";
CM_ SG_ 2149034734 P2D_CMD1_Reserved_01 "预留";
CM_ SG_ 2148958017 P2D_BUCK_FUN_RX_Byte1_01 "PC给DCDC的诊断报文字节0";
CM_ SG_ 2148958017 P2D_BUCK_FUN_RX_Byte2_01 "PC给DCDC的诊断报文字节1";
CM_ SG_ 2148958017 P2D_BUCK_FUN_RX_Byte3_01 "PC给DCDC的诊断报文字节2";
CM_ SG_ 2148958017 P2D_BUCK_FUN_RX_Byte4_01 "PC给DCDC的诊断报文字节3";
CM_ SG_ 2148958017 P2D_BUCK_FUN_RX_Byte5_01 "PC给DCDC的诊断报文字节4";
CM_ SG_ 2148958017 P2D_BUCK_FUN_RX_Byte6_01 "PC给DCDC的诊断报文字节5";
CM_ SG_ 2148958017 P2D_BUCK_FUN_RX_Byte7_01 "PC给DCDC的诊断报文字节6";
CM_ SG_ 2148958017 P2D_BUCK_FUN_RX_Byte8_01 "PC给DCDC的诊断报文字节7";
CM_ SG_ 2148958018 P2D_BUCK_FUN_RX_Byte1_02 "PC给DCDC的诊断报文字节0";
CM_ SG_ 2148958018 P2D_BUCK_FUN_RX_Byte2_02 "PC给DCDC的诊断报文字节1";
CM_ SG_ 2148958018 P2D_BUCK_FUN_RX_Byte3_02 "PC给DCDC的诊断报文字节2";
CM_ SG_ 2148958018 P2D_BUCK_FUN_RX_Byte4_02 "PC给DCDC的诊断报文字节3";
CM_ SG_ 2148958018 P2D_BUCK_FUN_RX_Byte5_02 "PC给DCDC的诊断报文字节4";
CM_ SG_ 2148958018 P2D_BUCK_FUN_RX_Byte6_02 "PC给DCDC的诊断报文字节5";
CM_ SG_ 2148958018 P2D_BUCK_FUN_RX_Byte7_02 "PC给DCDC的诊断报文字节6";
CM_ SG_ 2148958018 P2D_BUCK_FUN_RX_Byte8_02 "PC给DCDC的诊断报文字节7";
CM_ SG_ 2148958019 P2D_BUCK_FUN_RX_Byte1_03 "PC给DCDC的诊断报文字节0";
CM_ SG_ 2148958019 P2D_BUCK_FUN_RX_Byte2_03 "PC给DCDC的诊断报文字节1";
CM_ SG_ 2148958019 P2D_BUCK_FUN_RX_Byte3_03 "PC给DCDC的诊断报文字节2";
CM_ SG_ 2148958019 P2D_BUCK_FUN_RX_Byte4_03 "PC给DCDC的诊断报文字节3";
CM_ SG_ 2148958019 P2D_BUCK_FUN_RX_Byte5_03 "PC给DCDC的诊断报文字节4";
CM_ SG_ 2148958019 P2D_BUCK_FUN_RX_Byte6_03 "PC给DCDC的诊断报文字节5";
CM_ SG_ 2148958019 P2D_BUCK_FUN_RX_Byte7_03 "PC给DCDC的诊断报文字节6";
CM_ SG_ 2148958019 P2D_BUCK_FUN_RX_Byte8_03 "PC给DCDC的诊断报文字节7";
CM_ SG_ 2148958020 P2D_BUCK_FUN_RX_Byte1_04 "PC给DCDC的诊断报文字节0";
CM_ SG_ 2148958020 P2D_BUCK_FUN_RX_Byte2_04 "PC给DCDC的诊断报文字节1";
CM_ SG_ 2148958020 P2D_BUCK_FUN_RX_Byte3_04 "PC给DCDC的诊断报文字节2";
CM_ SG_ 2148958020 P2D_BUCK_FUN_RX_Byte4_04 "PC给DCDC的诊断报文字节3";
CM_ SG_ 2148958020 P2D_BUCK_FUN_RX_Byte5_04 "PC给DCDC的诊断报文字节4";
CM_ SG_ 2148958020 P2D_BUCK_FUN_RX_Byte6_04 "PC给DCDC的诊断报文字节5";
CM_ SG_ 2148958020 P2D_BUCK_FUN_RX_Byte7_04 "PC给DCDC的诊断报文字节6";
CM_ SG_ 2148958020 P2D_BUCK_FUN_RX_Byte8_04 "PC给DCDC的诊断报文字节7";
CM_ SG_ 2148958021 P2D_BUCK_FUN_RX_Byte1_05 "PC给DCDC的诊断报文字节0";
CM_ SG_ 2148958021 P2D_BUCK_FUN_RX_Byte2_05 "PC给DCDC的诊断报文字节1";
CM_ SG_ 2148958021 P2D_BUCK_FUN_RX_Byte3_05 "PC给DCDC的诊断报文字节2";
CM_ SG_ 2148958021 P2D_BUCK_FUN_RX_Byte4_05 "PC给DCDC的诊断报文字节3";
CM_ SG_ 2148958021 P2D_BUCK_FUN_RX_Byte5_05 "PC给DCDC的诊断报文字节4";
CM_ SG_ 2148958021 P2D_BUCK_FUN_RX_Byte6_05 "PC给DCDC的诊断报文字节5";
CM_ SG_ 2148958021 P2D_BUCK_FUN_RX_Byte7_05 "PC给DCDC的诊断报文字节6";
CM_ SG_ 2148958021 P2D_BUCK_FUN_RX_Byte8_05 "PC给DCDC的诊断报文字节7";
CM_ SG_ 2148958022 P2D_BUCK_FUN_RX_Byte1_06 "PC给DCDC的诊断报文字节0";
CM_ SG_ 2148958022 P2D_BUCK_FUN_RX_Byte2_06 "PC给DCDC的诊断报文字节1";
CM_ SG_ 2148958022 P2D_BUCK_FUN_RX_Byte3_06 "PC给DCDC的诊断报文字节2";
CM_ SG_ 2148958022 P2D_BUCK_FUN_RX_Byte4_06 "PC给DCDC的诊断报文字节3";
CM_ SG_ 2148958022 P2D_BUCK_FUN_RX_Byte5_06 "PC给DCDC的诊断报文字节4";
CM_ SG_ 2148958022 P2D_BUCK_FUN_RX_Byte6_06 "PC给DCDC的诊断报文字节5";
CM_ SG_ 2148958022 P2D_BUCK_FUN_RX_Byte7_06 "PC给DCDC的诊断报文字节6";
CM_ SG_ 2148958022 P2D_BUCK_FUN_RX_Byte8_06 "PC给DCDC的诊断报文字节7";
CM_ SG_ 2148958023 P2D_BUCK_FUN_RX_Byte1_07 "PC给DCDC的诊断报文字节0";
CM_ SG_ 2148958023 P2D_BUCK_FUN_RX_Byte2_07 "PC给DCDC的诊断报文字节1";
CM_ SG_ 2148958023 P2D_BUCK_FUN_RX_Byte3_07 "PC给DCDC的诊断报文字节2";
CM_ SG_ 2148958023 P2D_BUCK_FUN_RX_Byte4_07 "PC给DCDC的诊断报文字节3";
CM_ SG_ 2148958023 P2D_BUCK_FUN_RX_Byte5_07 "PC给DCDC的诊断报文字节4";
CM_ SG_ 2148958023 P2D_BUCK_FUN_RX_Byte6_07 "PC给DCDC的诊断报文字节5";
CM_ SG_ 2148958023 P2D_BUCK_FUN_RX_Byte7_07 "PC给DCDC的诊断报文字节6";
CM_ SG_ 2148958023 P2D_BUCK_FUN_RX_Byte8_07 "PC给DCDC的诊断报文字节7";
CM_ SG_ 2148958024 P2D_BUCK_FUN_RX_Byte1_08 "PC给DCDC的诊断报文字节0";
CM_ SG_ 2148958024 P2D_BUCK_FUN_RX_Byte2_08 "PC给DCDC的诊断报文字节1";
CM_ SG_ 2148958024 P2D_BUCK_FUN_RX_Byte3_08 "PC给DCDC的诊断报文字节2";
CM_ SG_ 2148958024 P2D_BUCK_FUN_RX_Byte4_08 "PC给DCDC的诊断报文字节3";
CM_ SG_ 2148958024 P2D_BUCK_FUN_RX_Byte5_08 "PC给DCDC的诊断报文字节4";
CM_ SG_ 2148958024 P2D_BUCK_FUN_RX_Byte6_08 "PC给DCDC的诊断报文字节5";
CM_ SG_ 2148958024 P2D_BUCK_FUN_RX_Byte7_08 "PC给DCDC的诊断报文字节6";
CM_ SG_ 2148958024 P2D_BUCK_FUN_RX_Byte8_08 "PC给DCDC的诊断报文字节7";
CM_ SG_ 2148958025 P2D_BUCK_FUN_RX_Byte1_09 "PC给DCDC的诊断报文字节0";
CM_ SG_ 2148958025 P2D_BUCK_FUN_RX_Byte2_09 "PC给DCDC的诊断报文字节1";
CM_ SG_ 2148958025 P2D_BUCK_FUN_RX_Byte3_09 "PC给DCDC的诊断报文字节2";
CM_ SG_ 2148958025 P2D_BUCK_FUN_RX_Byte4_09 "PC给DCDC的诊断报文字节3";
CM_ SG_ 2148958025 P2D_BUCK_FUN_RX_Byte5_09 "PC给DCDC的诊断报文字节4";
CM_ SG_ 2148958025 P2D_BUCK_FUN_RX_Byte6_09 "PC给DCDC的诊断报文字节5";
CM_ SG_ 2148958025 P2D_BUCK_FUN_RX_Byte7_09 "PC给DCDC的诊断报文字节6";
CM_ SG_ 2148958025 P2D_BUCK_FUN_RX_Byte8_09 "PC给DCDC的诊断报文字节7";
CM_ SG_ 2148958026 P2D_BUCK_FUN_RX_Byte1_10 "PC给DCDC的诊断报文字节0";
CM_ SG_ 2148958026 P2D_BUCK_FUN_RX_Byte2_10 "PC给DCDC的诊断报文字节1";
CM_ SG_ 2148958026 P2D_BUCK_FUN_RX_Byte3_10 "PC给DCDC的诊断报文字节2";
CM_ SG_ 2148958026 P2D_BUCK_FUN_RX_Byte4_10 "PC给DCDC的诊断报文字节3";
CM_ SG_ 2148958026 P2D_BUCK_FUN_RX_Byte5_10 "PC给DCDC的诊断报文字节4";
CM_ SG_ 2148958026 P2D_BUCK_FUN_RX_Byte6_10 "PC给DCDC的诊断报文字节5";
CM_ SG_ 2148958026 P2D_BUCK_FUN_RX_Byte7_10 "PC给DCDC的诊断报文字节6";
CM_ SG_ 2148958026 P2D_BUCK_FUN_RX_Byte8_10 "PC给DCDC的诊断报文字节7";
CM_ SG_ 2148958027 P2D_BUCK_FUN_RX_Byte1_11 "PC给DCDC的诊断报文字节0";
CM_ SG_ 2148958027 P2D_BUCK_FUN_RX_Byte2_11 "PC给DCDC的诊断报文字节1";
CM_ SG_ 2148958027 P2D_BUCK_FUN_RX_Byte3_11 "PC给DCDC的诊断报文字节2";
CM_ SG_ 2148958027 P2D_BUCK_FUN_RX_Byte4_11 "PC给DCDC的诊断报文字节3";
CM_ SG_ 2148958027 P2D_BUCK_FUN_RX_Byte5_11 "PC给DCDC的诊断报文字节4";
CM_ SG_ 2148958027 P2D_BUCK_FUN_RX_Byte6_11 "PC给DCDC的诊断报文字节5";
CM_ SG_ 2148958027 P2D_BUCK_FUN_RX_Byte7_11 "PC给DCDC的诊断报文字节6";
CM_ SG_ 2148958027 P2D_BUCK_FUN_RX_Byte8_11 "PC给DCDC的诊断报文字节7";
CM_ SG_ 2148958028 P2D_BUCK_FUN_RX_Byte1_12 "PC给DCDC的诊断报文字节0";
CM_ SG_ 2148958028 P2D_BUCK_FUN_RX_Byte2_12 "PC给DCDC的诊断报文字节1";
CM_ SG_ 2148958028 P2D_BUCK_FUN_RX_Byte3_12 "PC给DCDC的诊断报文字节2";
CM_ SG_ 2148958028 P2D_BUCK_FUN_RX_Byte4_12 "PC给DCDC的诊断报文字节3";
CM_ SG_ 2148958028 P2D_BUCK_FUN_RX_Byte5_12 "PC给DCDC的诊断报文字节4";
CM_ SG_ 2148958028 P2D_BUCK_FUN_RX_Byte6_12 "PC给DCDC的诊断报文字节5";
CM_ SG_ 2148958028 P2D_BUCK_FUN_RX_Byte7_12 "PC给DCDC的诊断报文字节6";
CM_ SG_ 2148958028 P2D_BUCK_FUN_RX_Byte8_12 "PC给DCDC的诊断报文字节7";
CM_ SG_ 2148958029 P2D_BUCK_FUN_RX_Byte1_13 "PC给DCDC的诊断报文字节0";
CM_ SG_ 2148958029 P2D_BUCK_FUN_RX_Byte2_13 "PC给DCDC的诊断报文字节1";
CM_ SG_ 2148958029 P2D_BUCK_FUN_RX_Byte3_13 "PC给DCDC的诊断报文字节2";
CM_ SG_ 2148958029 P2D_BUCK_FUN_RX_Byte4_13 "PC给DCDC的诊断报文字节3";
CM_ SG_ 2148958029 P2D_BUCK_FUN_RX_Byte5_13 "PC给DCDC的诊断报文字节4";
CM_ SG_ 2148958029 P2D_BUCK_FUN_RX_Byte6_13 "PC给DCDC的诊断报文字节5";
CM_ SG_ 2148958029 P2D_BUCK_FUN_RX_Byte7_13 "PC给DCDC的诊断报文字节6";
CM_ SG_ 2148958029 P2D_BUCK_FUN_RX_Byte8_13 "PC给DCDC的诊断报文字节7";
CM_ SG_ 2148958030 P2D_BUCK_FUN_RX_Byte1_14 "PC给DCDC的诊断报文字节0";
CM_ SG_ 2148958030 P2D_BUCK_FUN_RX_Byte2_14 "PC给DCDC的诊断报文字节1";
CM_ SG_ 2148958030 P2D_BUCK_FUN_RX_Byte3_14 "PC给DCDC的诊断报文字节2";
CM_ SG_ 2148958030 P2D_BUCK_FUN_RX_Byte4_14 "PC给DCDC的诊断报文字节3";
CM_ SG_ 2148958030 P2D_BUCK_FUN_RX_Byte5_14 "PC给DCDC的诊断报文字节4";
CM_ SG_ 2148958030 P2D_BUCK_FUN_RX_Byte6_14 "PC给DCDC的诊断报文字节5";
CM_ SG_ 2148958030 P2D_BUCK_FUN_RX_Byte7_14 "PC给DCDC的诊断报文字节6";
CM_ SG_ 2148958030 P2D_BUCK_FUN_RX_Byte8_14 "PC给DCDC的诊断报文字节7";
CM_ SG_ 2148958031 P2D_BUCK_FUN_RX_Byte1_15 "PC给DCDC的诊断报文字节0";
CM_ SG_ 2148958031 P2D_BUCK_FUN_RX_Byte2_15 "PC给DCDC的诊断报文字节1";
CM_ SG_ 2148958031 P2D_BUCK_FUN_RX_Byte3_15 "PC给DCDC的诊断报文字节2";
CM_ SG_ 2148958031 P2D_BUCK_FUN_RX_Byte4_15 "PC给DCDC的诊断报文字节3";
CM_ SG_ 2148958031 P2D_BUCK_FUN_RX_Byte5_15 "PC给DCDC的诊断报文字节4";
CM_ SG_ 2148958031 P2D_BUCK_FUN_RX_Byte6_15 "PC给DCDC的诊断报文字节5";
CM_ SG_ 2148958031 P2D_BUCK_FUN_RX_Byte7_15 "PC给DCDC的诊断报文字节6";
CM_ SG_ 2148958031 P2D_BUCK_FUN_RX_Byte8_15 "PC给DCDC的诊断报文字节7";
CM_ SG_ 2148958032 P2D_BUCK_FUN_RX_Byte1_16 "PC给DCDC的诊断报文字节0";
CM_ SG_ 2148958032 P2D_BUCK_FUN_RX_Byte2_16 "PC给DCDC的诊断报文字节1";
CM_ SG_ 2148958032 P2D_BUCK_FUN_RX_Byte3_16 "PC给DCDC的诊断报文字节2";
CM_ SG_ 2148958032 P2D_BUCK_FUN_RX_Byte4_16 "PC给DCDC的诊断报文字节3";
CM_ SG_ 2148958032 P2D_BUCK_FUN_RX_Byte5_16 "PC给DCDC的诊断报文字节4";
CM_ SG_ 2148958032 P2D_BUCK_FUN_RX_Byte6_16 "PC给DCDC的诊断报文字节5";
CM_ SG_ 2148958032 P2D_BUCK_FUN_RX_Byte7_16 "PC给DCDC的诊断报文字节6";
CM_ SG_ 2148958032 P2D_BUCK_FUN_RX_Byte8_16 "PC给DCDC的诊断报文字节7";
CM_ SG_ 2148958033 P2D_BUCK_FUN_RX_Byte1_17 "PC给DCDC的诊断报文字节0";
CM_ SG_ 2148958033 P2D_BUCK_FUN_RX_Byte2_17 "PC给DCDC的诊断报文字节1";
CM_ SG_ 2148958033 P2D_BUCK_FUN_RX_Byte3_17 "PC给DCDC的诊断报文字节2";
CM_ SG_ 2148958033 P2D_BUCK_FUN_RX_Byte4_17 "PC给DCDC的诊断报文字节3";
CM_ SG_ 2148958033 P2D_BUCK_FUN_RX_Byte5_17 "PC给DCDC的诊断报文字节4";
CM_ SG_ 2148958033 P2D_BUCK_FUN_RX_Byte6_17 "PC给DCDC的诊断报文字节5";
CM_ SG_ 2148958033 P2D_BUCK_FUN_RX_Byte7_17 "PC给DCDC的诊断报文字节6";
CM_ SG_ 2148958033 P2D_BUCK_FUN_RX_Byte8_17 "PC给DCDC的诊断报文字节7";
CM_ SG_ 2148958034 P2D_BUCK_FUN_RX_Byte1_18 "PC给DCDC的诊断报文字节0";
CM_ SG_ 2148958034 P2D_BUCK_FUN_RX_Byte2_18 "PC给DCDC的诊断报文字节1";
CM_ SG_ 2148958034 P2D_BUCK_FUN_RX_Byte3_18 "PC给DCDC的诊断报文字节2";
CM_ SG_ 2148958034 P2D_BUCK_FUN_RX_Byte4_18 "PC给DCDC的诊断报文字节3";
CM_ SG_ 2148958034 P2D_BUCK_FUN_RX_Byte5_18 "PC给DCDC的诊断报文字节4";
CM_ SG_ 2148958034 P2D_BUCK_FUN_RX_Byte6_18 "PC给DCDC的诊断报文字节5";
CM_ SG_ 2148958034 P2D_BUCK_FUN_RX_Byte7_18 "PC给DCDC的诊断报文字节6";
CM_ SG_ 2148958034 P2D_BUCK_FUN_RX_Byte8_18 "PC给DCDC的诊断报文字节7";
CM_ SG_ 2148958035 P2D_BUCK_FUN_RX_Byte1_19 "PC给DCDC的诊断报文字节0";
CM_ SG_ 2148958035 P2D_BUCK_FUN_RX_Byte2_19 "PC给DCDC的诊断报文字节1";
CM_ SG_ 2148958035 P2D_BUCK_FUN_RX_Byte3_19 "PC给DCDC的诊断报文字节2";
CM_ SG_ 2148958035 P2D_BUCK_FUN_RX_Byte4_19 "PC给DCDC的诊断报文字节3";
CM_ SG_ 2148958035 P2D_BUCK_FUN_RX_Byte5_19 "PC给DCDC的诊断报文字节4";
CM_ SG_ 2148958035 P2D_BUCK_FUN_RX_Byte6_19 "PC给DCDC的诊断报文字节5";
CM_ SG_ 2148958035 P2D_BUCK_FUN_RX_Byte7_19 "PC给DCDC的诊断报文字节6";
CM_ SG_ 2148958035 P2D_BUCK_FUN_RX_Byte8_19 "PC给DCDC的诊断报文字节7";
CM_ SG_ 2148958036 P2D_BUCK_FUN_RX_Byte1_20 "PC给DCDC的诊断报文字节0";
CM_ SG_ 2148958036 P2D_BUCK_FUN_RX_Byte2_20 "PC给DCDC的诊断报文字节1";
CM_ SG_ 2148958036 P2D_BUCK_FUN_RX_Byte3_20 "PC给DCDC的诊断报文字节2";
CM_ SG_ 2148958036 P2D_BUCK_FUN_RX_Byte4_20 "PC给DCDC的诊断报文字节3";
CM_ SG_ 2148958036 P2D_BUCK_FUN_RX_Byte5_20 "PC给DCDC的诊断报文字节4";
CM_ SG_ 2148958036 P2D_BUCK_FUN_RX_Byte6_20 "PC给DCDC的诊断报文字节5";
CM_ SG_ 2148958036 P2D_BUCK_FUN_RX_Byte7_20 "PC给DCDC的诊断报文字节6";
CM_ SG_ 2148958036 P2D_BUCK_FUN_RX_Byte8_20 "PC给DCDC的诊断报文字节7";
CM_ SG_ 2148958037 P2D_BUCK_FUN_RX_Byte1_21 "PC给DCDC的诊断报文字节0";
CM_ SG_ 2148958037 P2D_BUCK_FUN_RX_Byte2_21 "PC给DCDC的诊断报文字节1";
CM_ SG_ 2148958037 P2D_BUCK_FUN_RX_Byte3_21 "PC给DCDC的诊断报文字节2";
CM_ SG_ 2148958037 P2D_BUCK_FUN_RX_Byte4_21 "PC给DCDC的诊断报文字节3";
CM_ SG_ 2148958037 P2D_BUCK_FUN_RX_Byte5_21 "PC给DCDC的诊断报文字节4";
CM_ SG_ 2148958037 P2D_BUCK_FUN_RX_Byte6_21 "PC给DCDC的诊断报文字节5";
CM_ SG_ 2148958037 P2D_BUCK_FUN_RX_Byte7_21 "PC给DCDC的诊断报文字节6";
CM_ SG_ 2148958037 P2D_BUCK_FUN_RX_Byte8_21 "PC给DCDC的诊断报文字节7";
CM_ SG_ 2148958038 P2D_BUCK_FUN_RX_Byte1_22 "PC给DCDC的诊断报文字节0";
CM_ SG_ 2148958038 P2D_BUCK_FUN_RX_Byte2_22 "PC给DCDC的诊断报文字节1";
CM_ SG_ 2148958038 P2D_BUCK_FUN_RX_Byte3_22 "PC给DCDC的诊断报文字节2";
CM_ SG_ 2148958038 P2D_BUCK_FUN_RX_Byte4_22 "PC给DCDC的诊断报文字节3";
CM_ SG_ 2148958038 P2D_BUCK_FUN_RX_Byte5_22 "PC给DCDC的诊断报文字节4";
CM_ SG_ 2148958038 P2D_BUCK_FUN_RX_Byte6_22 "PC给DCDC的诊断报文字节5";
CM_ SG_ 2148958038 P2D_BUCK_FUN_RX_Byte7_22 "PC给DCDC的诊断报文字节6";
CM_ SG_ 2148958038 P2D_BUCK_FUN_RX_Byte8_22 "PC给DCDC的诊断报文字节7";
CM_ SG_ 2148958039 P2D_BUCK_FUN_RX_Byte1_23 "PC给DCDC的诊断报文字节0";
CM_ SG_ 2148958039 P2D_BUCK_FUN_RX_Byte2_23 "PC给DCDC的诊断报文字节1";
CM_ SG_ 2148958039 P2D_BUCK_FUN_RX_Byte3_23 "PC给DCDC的诊断报文字节2";
CM_ SG_ 2148958039 P2D_BUCK_FUN_RX_Byte4_23 "PC给DCDC的诊断报文字节3";
CM_ SG_ 2148958039 P2D_BUCK_FUN_RX_Byte5_23 "PC给DCDC的诊断报文字节4";
CM_ SG_ 2148958039 P2D_BUCK_FUN_RX_Byte6_23 "PC给DCDC的诊断报文字节5";
CM_ SG_ 2148958039 P2D_BUCK_FUN_RX_Byte7_23 "PC给DCDC的诊断报文字节6";
CM_ SG_ 2148958039 P2D_BUCK_FUN_RX_Byte8_23 "PC给DCDC的诊断报文字节7";
CM_ SG_ 2148958040 P2D_BUCK_FUN_RX_Byte1_24 "PC给DCDC的诊断报文字节0";
CM_ SG_ 2148958040 P2D_BUCK_FUN_RX_Byte2_24 "PC给DCDC的诊断报文字节1";
CM_ SG_ 2148958040 P2D_BUCK_FUN_RX_Byte3_24 "PC给DCDC的诊断报文字节2";
CM_ SG_ 2148958040 P2D_BUCK_FUN_RX_Byte4_24 "PC给DCDC的诊断报文字节3";
CM_ SG_ 2148958040 P2D_BUCK_FUN_RX_Byte5_24 "PC给DCDC的诊断报文字节4";
CM_ SG_ 2148958040 P2D_BUCK_FUN_RX_Byte6_24 "PC给DCDC的诊断报文字节5";
CM_ SG_ 2148958040 P2D_BUCK_FUN_RX_Byte7_24 "PC给DCDC的诊断报文字节6";
CM_ SG_ 2148958040 P2D_BUCK_FUN_RX_Byte8_24 "PC给DCDC的诊断报文字节7";
CM_ SG_ 2148958041 P2D_BUCK_FUN_RX_Byte1_25 "PC给DCDC的诊断报文字节0";
CM_ SG_ 2148958041 P2D_BUCK_FUN_RX_Byte2_25 "PC给DCDC的诊断报文字节1";
CM_ SG_ 2148958041 P2D_BUCK_FUN_RX_Byte3_25 "PC给DCDC的诊断报文字节2";
CM_ SG_ 2148958041 P2D_BUCK_FUN_RX_Byte4_25 "PC给DCDC的诊断报文字节3";
CM_ SG_ 2148958041 P2D_BUCK_FUN_RX_Byte5_25 "PC给DCDC的诊断报文字节4";
CM_ SG_ 2148958041 P2D_BUCK_FUN_RX_Byte6_25 "PC给DCDC的诊断报文字节5";
CM_ SG_ 2148958041 P2D_BUCK_FUN_RX_Byte7_25 "PC给DCDC的诊断报文字节6";
CM_ SG_ 2148958041 P2D_BUCK_FUN_RX_Byte8_25 "PC给DCDC的诊断报文字节7";
CM_ SG_ 2148958042 P2D_BUCK_FUN_RX_Byte1_26 "PC给DCDC的诊断报文字节0";
CM_ SG_ 2148958042 P2D_BUCK_FUN_RX_Byte2_26 "PC给DCDC的诊断报文字节1";
CM_ SG_ 2148958042 P2D_BUCK_FUN_RX_Byte3_26 "PC给DCDC的诊断报文字节2";
CM_ SG_ 2148958042 P2D_BUCK_FUN_RX_Byte4_26 "PC给DCDC的诊断报文字节3";
CM_ SG_ 2148958042 P2D_BUCK_FUN_RX_Byte5_26 "PC给DCDC的诊断报文字节4";
CM_ SG_ 2148958042 P2D_BUCK_FUN_RX_Byte6_26 "PC给DCDC的诊断报文字节5";
CM_ SG_ 2148958042 P2D_BUCK_FUN_RX_Byte7_26 "PC给DCDC的诊断报文字节6";
CM_ SG_ 2148958042 P2D_BUCK_FUN_RX_Byte8_26 "PC给DCDC的诊断报文字节7";
CM_ SG_ 2148958043 P2D_BUCK_FUN_RX_Byte1_27 "PC给DCDC的诊断报文字节0";
CM_ SG_ 2148958043 P2D_BUCK_FUN_RX_Byte2_27 "PC给DCDC的诊断报文字节1";
CM_ SG_ 2148958043 P2D_BUCK_FUN_RX_Byte3_27 "PC给DCDC的诊断报文字节2";
CM_ SG_ 2148958043 P2D_BUCK_FUN_RX_Byte4_27 "PC给DCDC的诊断报文字节3";
CM_ SG_ 2148958043 P2D_BUCK_FUN_RX_Byte5_27 "PC给DCDC的诊断报文字节4";
CM_ SG_ 2148958043 P2D_BUCK_FUN_RX_Byte6_27 "PC给DCDC的诊断报文字节5";
CM_ SG_ 2148958043 P2D_BUCK_FUN_RX_Byte7_27 "PC给DCDC的诊断报文字节6";
CM_ SG_ 2148958043 P2D_BUCK_FUN_RX_Byte8_27 "PC给DCDC的诊断报文字节7";
CM_ SG_ 2148958044 P2D_BUCK_FUN_RX_Byte1_28 "PC给DCDC的诊断报文字节0";
CM_ SG_ 2148958044 P2D_BUCK_FUN_RX_Byte2_28 "PC给DCDC的诊断报文字节1";
CM_ SG_ 2148958044 P2D_BUCK_FUN_RX_Byte3_28 "PC给DCDC的诊断报文字节2";
CM_ SG_ 2148958044 P2D_BUCK_FUN_RX_Byte4_28 "PC给DCDC的诊断报文字节3";
CM_ SG_ 2148958044 P2D_BUCK_FUN_RX_Byte5_28 "PC给DCDC的诊断报文字节4";
CM_ SG_ 2148958044 P2D_BUCK_FUN_RX_Byte6_28 "PC给DCDC的诊断报文字节5";
CM_ SG_ 2148958044 P2D_BUCK_FUN_RX_Byte7_28 "PC给DCDC的诊断报文字节6";
CM_ SG_ 2148958044 P2D_BUCK_FUN_RX_Byte8_28 "PC给DCDC的诊断报文字节7";
CM_ SG_ 2148958045 P2D_BUCK_FUN_RX_Byte1_29 "PC给DCDC的诊断报文字节0";
CM_ SG_ 2148958045 P2D_BUCK_FUN_RX_Byte2_29 "PC给DCDC的诊断报文字节1";
CM_ SG_ 2148958045 P2D_BUCK_FUN_RX_Byte3_29 "PC给DCDC的诊断报文字节2";
CM_ SG_ 2148958045 P2D_BUCK_FUN_RX_Byte4_29 "PC给DCDC的诊断报文字节3";
CM_ SG_ 2148958045 P2D_BUCK_FUN_RX_Byte5_29 "PC给DCDC的诊断报文字节4";
CM_ SG_ 2148958045 P2D_BUCK_FUN_RX_Byte6_29 "PC给DCDC的诊断报文字节5";
CM_ SG_ 2148958045 P2D_BUCK_FUN_RX_Byte7_29 "PC给DCDC的诊断报文字节6";
CM_ SG_ 2148958045 P2D_BUCK_FUN_RX_Byte8_29 "PC给DCDC的诊断报文字节7";
CM_ SG_ 2148958046 P2D_BUCK_FUN_RX_Byte1_30 "PC给DCDC的诊断报文字节0";
CM_ SG_ 2148958046 P2D_BUCK_FUN_RX_Byte2_30 "PC给DCDC的诊断报文字节1";
CM_ SG_ 2148958046 P2D_BUCK_FUN_RX_Byte3_30 "PC给DCDC的诊断报文字节2";
CM_ SG_ 2148958046 P2D_BUCK_FUN_RX_Byte4_30 "PC给DCDC的诊断报文字节3";
CM_ SG_ 2148958046 P2D_BUCK_FUN_RX_Byte5_30 "PC给DCDC的诊断报文字节4";
CM_ SG_ 2148958046 P2D_BUCK_FUN_RX_Byte6_30 "PC给DCDC的诊断报文字节5";
CM_ SG_ 2148958046 P2D_BUCK_FUN_RX_Byte7_30 "PC给DCDC的诊断报文字节6";
CM_ SG_ 2148958046 P2D_BUCK_FUN_RX_Byte8_30 "PC给DCDC的诊断报文字节7";
CM_ SG_ 2148958047 P2D_BUCK_FUN_RX_Byte1_31 "PC给DCDC的诊断报文字节0";
CM_ SG_ 2148958047 P2D_BUCK_FUN_RX_Byte2_31 "PC给DCDC的诊断报文字节1";
CM_ SG_ 2148958047 P2D_BUCK_FUN_RX_Byte3_31 "PC给DCDC的诊断报文字节2";
CM_ SG_ 2148958047 P2D_BUCK_FUN_RX_Byte4_31 "PC给DCDC的诊断报文字节3";
CM_ SG_ 2148958047 P2D_BUCK_FUN_RX_Byte5_31 "PC给DCDC的诊断报文字节4";
CM_ SG_ 2148958047 P2D_BUCK_FUN_RX_Byte6_31 "PC给DCDC的诊断报文字节5";
CM_ SG_ 2148958047 P2D_BUCK_FUN_RX_Byte7_31 "PC给DCDC的诊断报文字节6";
CM_ SG_ 2148958047 P2D_BUCK_FUN_RX_Byte8_31 "PC给DCDC的诊断报文字节7";
CM_ SG_ 2148958048 P2D_BUCK_FUN_RX_Byte1_32 "PC给DCDC的诊断报文字节0";
CM_ SG_ 2148958048 P2D_BUCK_FUN_RX_Byte2_32 "PC给DCDC的诊断报文字节1";
CM_ SG_ 2148958048 P2D_BUCK_FUN_RX_Byte3_32 "PC给DCDC的诊断报文字节2";
CM_ SG_ 2148958048 P2D_BUCK_FUN_RX_Byte4_32 "PC给DCDC的诊断报文字节3";
CM_ SG_ 2148958048 P2D_BUCK_FUN_RX_Byte5_32 "PC给DCDC的诊断报文字节4";
CM_ SG_ 2148958048 P2D_BUCK_FUN_RX_Byte6_32 "PC给DCDC的诊断报文字节5";
CM_ SG_ 2148958048 P2D_BUCK_FUN_RX_Byte7_32 "PC给DCDC的诊断报文字节6";
CM_ SG_ 2148958048 P2D_BUCK_FUN_RX_Byte8_32 "PC给DCDC的诊断报文字节7";
CM_ SG_ 2148958049 P2D_BUCK_FUN_RX_Byte1_33 "PC给DCDC的诊断报文字节0";
CM_ SG_ 2148958049 P2D_BUCK_FUN_RX_Byte2_33 "PC给DCDC的诊断报文字节1";
CM_ SG_ 2148958049 P2D_BUCK_FUN_RX_Byte3_33 "PC给DCDC的诊断报文字节2";
CM_ SG_ 2148958049 P2D_BUCK_FUN_RX_Byte4_33 "PC给DCDC的诊断报文字节3";
CM_ SG_ 2148958049 P2D_BUCK_FUN_RX_Byte5_33 "PC给DCDC的诊断报文字节4";
CM_ SG_ 2148958049 P2D_BUCK_FUN_RX_Byte6_33 "PC给DCDC的诊断报文字节5";
CM_ SG_ 2148958049 P2D_BUCK_FUN_RX_Byte7_33 "PC给DCDC的诊断报文字节6";
CM_ SG_ 2148958049 P2D_BUCK_FUN_RX_Byte8_33 "PC给DCDC的诊断报文字节7";
CM_ SG_ 2148958050 P2D_BUCK_FUN_RX_Byte1_34 "PC给DCDC的诊断报文字节0";
CM_ SG_ 2148958050 P2D_BUCK_FUN_RX_Byte2_34 "PC给DCDC的诊断报文字节1";
CM_ SG_ 2148958050 P2D_BUCK_FUN_RX_Byte3_34 "PC给DCDC的诊断报文字节2";
CM_ SG_ 2148958050 P2D_BUCK_FUN_RX_Byte4_34 "PC给DCDC的诊断报文字节3";
CM_ SG_ 2148958050 P2D_BUCK_FUN_RX_Byte5_34 "PC给DCDC的诊断报文字节4";
CM_ SG_ 2148958050 P2D_BUCK_FUN_RX_Byte6_34 "PC给DCDC的诊断报文字节5";
CM_ SG_ 2148958050 P2D_BUCK_FUN_RX_Byte7_34 "PC给DCDC的诊断报文字节6";
CM_ SG_ 2148958050 P2D_BUCK_FUN_RX_Byte8_34 "PC给DCDC的诊断报文字节7";
CM_ SG_ 2148958051 P2D_BUCK_FUN_RX_Byte1_35 "PC给DCDC的诊断报文字节0";
CM_ SG_ 2148958051 P2D_BUCK_FUN_RX_Byte2_35 "PC给DCDC的诊断报文字节1";
CM_ SG_ 2148958051 P2D_BUCK_FUN_RX_Byte3_35 "PC给DCDC的诊断报文字节2";
CM_ SG_ 2148958051 P2D_BUCK_FUN_RX_Byte4_35 "PC给DCDC的诊断报文字节3";
CM_ SG_ 2148958051 P2D_BUCK_FUN_RX_Byte5_35 "PC给DCDC的诊断报文字节4";
CM_ SG_ 2148958051 P2D_BUCK_FUN_RX_Byte6_35 "PC给DCDC的诊断报文字节5";
CM_ SG_ 2148958051 P2D_BUCK_FUN_RX_Byte7_35 "PC给DCDC的诊断报文字节6";
CM_ SG_ 2148958051 P2D_BUCK_FUN_RX_Byte8_35 "PC给DCDC的诊断报文字节7";
CM_ SG_ 2148958052 P2D_BUCK_FUN_RX_Byte1_36 "PC给DCDC的诊断报文字节0";
CM_ SG_ 2148958052 P2D_BUCK_FUN_RX_Byte2_36 "PC给DCDC的诊断报文字节1";
CM_ SG_ 2148958052 P2D_BUCK_FUN_RX_Byte3_36 "PC给DCDC的诊断报文字节2";
CM_ SG_ 2148958052 P2D_BUCK_FUN_RX_Byte4_36 "PC给DCDC的诊断报文字节3";
CM_ SG_ 2148958052 P2D_BUCK_FUN_RX_Byte5_36 "PC给DCDC的诊断报文字节4";
CM_ SG_ 2148958052 P2D_BUCK_FUN_RX_Byte6_36 "PC给DCDC的诊断报文字节5";
CM_ SG_ 2148958052 P2D_BUCK_FUN_RX_Byte7_36 "PC给DCDC的诊断报文字节6";
CM_ SG_ 2148958052 P2D_BUCK_FUN_RX_Byte8_36 "PC给DCDC的诊断报文字节7";
CM_ SG_ 2148958053 P2D_BUCK_FUN_RX_Byte1_37 "PC给DCDC的诊断报文字节0";
CM_ SG_ 2148958053 P2D_BUCK_FUN_RX_Byte2_37 "PC给DCDC的诊断报文字节1";
CM_ SG_ 2148958053 P2D_BUCK_FUN_RX_Byte3_37 "PC给DCDC的诊断报文字节2";
CM_ SG_ 2148958053 P2D_BUCK_FUN_RX_Byte4_37 "PC给DCDC的诊断报文字节3";
CM_ SG_ 2148958053 P2D_BUCK_FUN_RX_Byte5_37 "PC给DCDC的诊断报文字节4";
CM_ SG_ 2148958053 P2D_BUCK_FUN_RX_Byte6_37 "PC给DCDC的诊断报文字节5";
CM_ SG_ 2148958053 P2D_BUCK_FUN_RX_Byte7_37 "PC给DCDC的诊断报文字节6";
CM_ SG_ 2148958053 P2D_BUCK_FUN_RX_Byte8_37 "PC给DCDC的诊断报文字节7";
CM_ SG_ 2148958054 P2D_BUCK_FUN_RX_Byte1_38 "PC给DCDC的诊断报文字节0";
CM_ SG_ 2148958054 P2D_BUCK_FUN_RX_Byte2_38 "PC给DCDC的诊断报文字节1";
CM_ SG_ 2148958054 P2D_BUCK_FUN_RX_Byte3_38 "PC给DCDC的诊断报文字节2";
CM_ SG_ 2148958054 P2D_BUCK_FUN_RX_Byte4_38 "PC给DCDC的诊断报文字节3";
CM_ SG_ 2148958054 P2D_BUCK_FUN_RX_Byte5_38 "PC给DCDC的诊断报文字节4";
CM_ SG_ 2148958054 P2D_BUCK_FUN_RX_Byte6_38 "PC给DCDC的诊断报文字节5";
CM_ SG_ 2148958054 P2D_BUCK_FUN_RX_Byte7_38 "PC给DCDC的诊断报文字节6";
CM_ SG_ 2148958054 P2D_BUCK_FUN_RX_Byte8_38 "PC给DCDC的诊断报文字节7";
CM_ SG_ 2148958055 P2D_BUCK_FUN_RX_Byte1_39 "PC给DCDC的诊断报文字节0";
CM_ SG_ 2148958055 P2D_BUCK_FUN_RX_Byte2_39 "PC给DCDC的诊断报文字节1";
CM_ SG_ 2148958055 P2D_BUCK_FUN_RX_Byte3_39 "PC给DCDC的诊断报文字节2";
CM_ SG_ 2148958055 P2D_BUCK_FUN_RX_Byte4_39 "PC给DCDC的诊断报文字节3";
CM_ SG_ 2148958055 P2D_BUCK_FUN_RX_Byte5_39 "PC给DCDC的诊断报文字节4";
CM_ SG_ 2148958055 P2D_BUCK_FUN_RX_Byte6_39 "PC给DCDC的诊断报文字节5";
CM_ SG_ 2148958055 P2D_BUCK_FUN_RX_Byte7_39 "PC给DCDC的诊断报文字节6";
CM_ SG_ 2148958055 P2D_BUCK_FUN_RX_Byte8_39 "PC给DCDC的诊断报文字节7";
CM_ SG_ 2148958056 P2D_BUCK_FUN_RX_Byte1_40 "PC给DCDC的诊断报文字节0";
CM_ SG_ 2148958056 P2D_BUCK_FUN_RX_Byte2_40 "PC给DCDC的诊断报文字节1";
CM_ SG_ 2148958056 P2D_BUCK_FUN_RX_Byte3_40 "PC给DCDC的诊断报文字节2";
CM_ SG_ 2148958056 P2D_BUCK_FUN_RX_Byte4_40 "PC给DCDC的诊断报文字节3";
CM_ SG_ 2148958056 P2D_BUCK_FUN_RX_Byte5_40 "PC给DCDC的诊断报文字节4";
CM_ SG_ 2148958056 P2D_BUCK_FUN_RX_Byte6_40 "PC给DCDC的诊断报文字节5";
CM_ SG_ 2148958056 P2D_BUCK_FUN_RX_Byte7_40 "PC给DCDC的诊断报文字节6";
CM_ SG_ 2148958056 P2D_BUCK_FUN_RX_Byte8_40 "PC给DCDC的诊断报文字节7";
CM_ SG_ 2148958057 P2D_BUCK_FUN_RX_Byte1_41 "PC给DCDC的诊断报文字节0";
CM_ SG_ 2148958057 P2D_BUCK_FUN_RX_Byte2_41 "PC给DCDC的诊断报文字节1";
CM_ SG_ 2148958057 P2D_BUCK_FUN_RX_Byte3_41 "PC给DCDC的诊断报文字节2";
CM_ SG_ 2148958057 P2D_BUCK_FUN_RX_Byte4_41 "PC给DCDC的诊断报文字节3";
CM_ SG_ 2148958057 P2D_BUCK_FUN_RX_Byte5_41 "PC给DCDC的诊断报文字节4";
CM_ SG_ 2148958057 P2D_BUCK_FUN_RX_Byte6_41 "PC给DCDC的诊断报文字节5";
CM_ SG_ 2148958057 P2D_BUCK_FUN_RX_Byte7_41 "PC给DCDC的诊断报文字节6";
CM_ SG_ 2148958057 P2D_BUCK_FUN_RX_Byte8_41 "PC给DCDC的诊断报文字节7";
CM_ SG_ 2148958058 P2D_BUCK_FUN_RX_Byte1_42 "PC给DCDC的诊断报文字节0";
CM_ SG_ 2148958058 P2D_BUCK_FUN_RX_Byte2_42 "PC给DCDC的诊断报文字节1";
CM_ SG_ 2148958058 P2D_BUCK_FUN_RX_Byte3_42 "PC给DCDC的诊断报文字节2";
CM_ SG_ 2148958058 P2D_BUCK_FUN_RX_Byte4_42 "PC给DCDC的诊断报文字节3";
CM_ SG_ 2148958058 P2D_BUCK_FUN_RX_Byte5_42 "PC给DCDC的诊断报文字节4";
CM_ SG_ 2148958058 P2D_BUCK_FUN_RX_Byte6_42 "PC给DCDC的诊断报文字节5";
CM_ SG_ 2148958058 P2D_BUCK_FUN_RX_Byte7_42 "PC给DCDC的诊断报文字节6";
CM_ SG_ 2148958058 P2D_BUCK_FUN_RX_Byte8_42 "PC给DCDC的诊断报文字节7";
CM_ SG_ 2148958059 P2D_BUCK_FUN_RX_Byte1_43 "PC给DCDC的诊断报文字节0";
CM_ SG_ 2148958059 P2D_BUCK_FUN_RX_Byte2_43 "PC给DCDC的诊断报文字节1";
CM_ SG_ 2148958059 P2D_BUCK_FUN_RX_Byte3_43 "PC给DCDC的诊断报文字节2";
CM_ SG_ 2148958059 P2D_BUCK_FUN_RX_Byte4_43 "PC给DCDC的诊断报文字节3";
CM_ SG_ 2148958059 P2D_BUCK_FUN_RX_Byte5_43 "PC给DCDC的诊断报文字节4";
CM_ SG_ 2148958059 P2D_BUCK_FUN_RX_Byte6_43 "PC给DCDC的诊断报文字节5";
CM_ SG_ 2148958059 P2D_BUCK_FUN_RX_Byte7_43 "PC给DCDC的诊断报文字节6";
CM_ SG_ 2148958059 P2D_BUCK_FUN_RX_Byte8_43 "PC给DCDC的诊断报文字节7";
CM_ SG_ 2148958060 P2D_BUCK_FUN_RX_Byte1_44 "PC给DCDC的诊断报文字节0";
CM_ SG_ 2148958060 P2D_BUCK_FUN_RX_Byte2_44 "PC给DCDC的诊断报文字节1";
CM_ SG_ 2148958060 P2D_BUCK_FUN_RX_Byte3_44 "PC给DCDC的诊断报文字节2";
CM_ SG_ 2148958060 P2D_BUCK_FUN_RX_Byte4_44 "PC给DCDC的诊断报文字节3";
CM_ SG_ 2148958060 P2D_BUCK_FUN_RX_Byte5_44 "PC给DCDC的诊断报文字节4";
CM_ SG_ 2148958060 P2D_BUCK_FUN_RX_Byte6_44 "PC给DCDC的诊断报文字节5";
CM_ SG_ 2148958060 P2D_BUCK_FUN_RX_Byte7_44 "PC给DCDC的诊断报文字节6";
CM_ SG_ 2148958060 P2D_BUCK_FUN_RX_Byte8_44 "PC给DCDC的诊断报文字节7";
CM_ SG_ 2148958061 P2D_BUCK_FUN_RX_Byte1_45 "PC给DCDC的诊断报文字节0";
CM_ SG_ 2148958061 P2D_BUCK_FUN_RX_Byte2_45 "PC给DCDC的诊断报文字节1";
CM_ SG_ 2148958061 P2D_BUCK_FUN_RX_Byte3_45 "PC给DCDC的诊断报文字节2";
CM_ SG_ 2148958061 P2D_BUCK_FUN_RX_Byte4_45 "PC给DCDC的诊断报文字节3";
CM_ SG_ 2148958061 P2D_BUCK_FUN_RX_Byte5_45 "PC给DCDC的诊断报文字节4";
CM_ SG_ 2148958061 P2D_BUCK_FUN_RX_Byte6_45 "PC给DCDC的诊断报文字节5";
CM_ SG_ 2148958061 P2D_BUCK_FUN_RX_Byte7_45 "PC给DCDC的诊断报文字节6";
CM_ SG_ 2148958061 P2D_BUCK_FUN_RX_Byte8_45 "PC给DCDC的诊断报文字节7";
CM_ SG_ 2148958062 P2D_BUCK_FUN_RX_Byte1_46 "PC给DCDC的诊断报文字节0";
CM_ SG_ 2148958062 P2D_BUCK_FUN_RX_Byte2_46 "PC给DCDC的诊断报文字节1";
CM_ SG_ 2148958062 P2D_BUCK_FUN_RX_Byte3_46 "PC给DCDC的诊断报文字节2";
CM_ SG_ 2148958062 P2D_BUCK_FUN_RX_Byte4_46 "PC给DCDC的诊断报文字节3";
CM_ SG_ 2148958062 P2D_BUCK_FUN_RX_Byte5_46 "PC给DCDC的诊断报文字节4";
CM_ SG_ 2148958062 P2D_BUCK_FUN_RX_Byte6_46 "PC给DCDC的诊断报文字节5";
CM_ SG_ 2148958062 P2D_BUCK_FUN_RX_Byte7_46 "PC给DCDC的诊断报文字节6";
CM_ SG_ 2148958062 P2D_BUCK_FUN_RX_Byte8_46 "PC给DCDC的诊断报文字节7";
CM_ SG_ 2148958063 P2D_BUCK_FUN_RX_Byte1_47 "PC给DCDC的诊断报文字节0";
CM_ SG_ 2148958063 P2D_BUCK_FUN_RX_Byte2_47 "PC给DCDC的诊断报文字节1";
CM_ SG_ 2148958063 P2D_BUCK_FUN_RX_Byte3_47 "PC给DCDC的诊断报文字节2";
CM_ SG_ 2148958063 P2D_BUCK_FUN_RX_Byte4_47 "PC给DCDC的诊断报文字节3";
CM_ SG_ 2148958063 P2D_BUCK_FUN_RX_Byte5_47 "PC给DCDC的诊断报文字节4";
CM_ SG_ 2148958063 P2D_BUCK_FUN_RX_Byte6_47 "PC给DCDC的诊断报文字节5";
CM_ SG_ 2148958063 P2D_BUCK_FUN_RX_Byte7_47 "PC给DCDC的诊断报文字节6";
CM_ SG_ 2148958063 P2D_BUCK_FUN_RX_Byte8_47 "PC给DCDC的诊断报文字节7";
CM_ SG_ 2148958064 P2D_BUCK_FUN_RX_Byte1_48 "PC给DCDC的诊断报文字节0";
CM_ SG_ 2148958064 P2D_BUCK_FUN_RX_Byte2_48 "PC给DCDC的诊断报文字节1";
CM_ SG_ 2148958064 P2D_BUCK_FUN_RX_Byte3_48 "PC给DCDC的诊断报文字节2";
CM_ SG_ 2148958064 P2D_BUCK_FUN_RX_Byte4_48 "PC给DCDC的诊断报文字节3";
CM_ SG_ 2148958064 P2D_BUCK_FUN_RX_Byte5_48 "PC给DCDC的诊断报文字节4";
CM_ SG_ 2148958064 P2D_BUCK_FUN_RX_Byte6_48 "PC给DCDC的诊断报文字节5";
CM_ SG_ 2148958064 P2D_BUCK_FUN_RX_Byte7_48 "PC给DCDC的诊断报文字节6";
CM_ SG_ 2148958064 P2D_BUCK_FUN_RX_Byte8_48 "PC给DCDC的诊断报文字节7";
CM_ SG_ 2148958065 P2D_BUCK_FUN_RX_Byte1_49 "PC给DCDC的诊断报文字节0";
CM_ SG_ 2148958065 P2D_BUCK_FUN_RX_Byte2_49 "PC给DCDC的诊断报文字节1";
CM_ SG_ 2148958065 P2D_BUCK_FUN_RX_Byte3_49 "PC给DCDC的诊断报文字节2";
CM_ SG_ 2148958065 P2D_BUCK_FUN_RX_Byte4_49 "PC给DCDC的诊断报文字节3";
CM_ SG_ 2148958065 P2D_BUCK_FUN_RX_Byte5_49 "PC给DCDC的诊断报文字节4";
CM_ SG_ 2148958065 P2D_BUCK_FUN_RX_Byte6_49 "PC给DCDC的诊断报文字节5";
CM_ SG_ 2148958065 P2D_BUCK_FUN_RX_Byte7_49 "PC给DCDC的诊断报文字节6";
CM_ SG_ 2148958065 P2D_BUCK_FUN_RX_Byte8_49 "PC给DCDC的诊断报文字节7";
CM_ SG_ 2148958066 P2D_BUCK_FUN_RX_Byte1_50 "PC给DCDC的诊断报文字节0";
CM_ SG_ 2148958066 P2D_BUCK_FUN_RX_Byte2_50 "PC给DCDC的诊断报文字节1";
CM_ SG_ 2148958066 P2D_BUCK_FUN_RX_Byte3_50 "PC给DCDC的诊断报文字节2";
CM_ SG_ 2148958066 P2D_BUCK_FUN_RX_Byte4_50 "PC给DCDC的诊断报文字节3";
CM_ SG_ 2148958066 P2D_BUCK_FUN_RX_Byte5_50 "PC给DCDC的诊断报文字节4";
CM_ SG_ 2148958066 P2D_BUCK_FUN_RX_Byte6_50 "PC给DCDC的诊断报文字节5";
CM_ SG_ 2148958066 P2D_BUCK_FUN_RX_Byte7_50 "PC给DCDC的诊断报文字节6";
CM_ SG_ 2148958066 P2D_BUCK_FUN_RX_Byte8_50 "PC给DCDC的诊断报文字节7";
CM_ SG_ 2148958067 P2D_BUCK_FUN_RX_Byte1_51 "PC给DCDC的诊断报文字节0";
CM_ SG_ 2148958067 P2D_BUCK_FUN_RX_Byte2_51 "PC给DCDC的诊断报文字节1";
CM_ SG_ 2148958067 P2D_BUCK_FUN_RX_Byte3_51 "PC给DCDC的诊断报文字节2";
CM_ SG_ 2148958067 P2D_BUCK_FUN_RX_Byte4_51 "PC给DCDC的诊断报文字节3";
CM_ SG_ 2148958067 P2D_BUCK_FUN_RX_Byte5_51 "PC给DCDC的诊断报文字节4";
CM_ SG_ 2148958067 P2D_BUCK_FUN_RX_Byte6_51 "PC给DCDC的诊断报文字节5";
CM_ SG_ 2148958067 P2D_BUCK_FUN_RX_Byte7_51 "PC给DCDC的诊断报文字节6";
CM_ SG_ 2148958067 P2D_BUCK_FUN_RX_Byte8_51 "PC给DCDC的诊断报文字节7";
CM_ SG_ 2148958068 P2D_BUCK_FUN_RX_Byte1_52 "PC给DCDC的诊断报文字节0";
CM_ SG_ 2148958068 P2D_BUCK_FUN_RX_Byte2_52 "PC给DCDC的诊断报文字节1";
CM_ SG_ 2148958068 P2D_BUCK_FUN_RX_Byte3_52 "PC给DCDC的诊断报文字节2";
CM_ SG_ 2148958068 P2D_BUCK_FUN_RX_Byte4_52 "PC给DCDC的诊断报文字节3";
CM_ SG_ 2148958068 P2D_BUCK_FUN_RX_Byte5_52 "PC给DCDC的诊断报文字节4";
CM_ SG_ 2148958068 P2D_BUCK_FUN_RX_Byte6_52 "PC给DCDC的诊断报文字节5";
CM_ SG_ 2148958068 P2D_BUCK_FUN_RX_Byte7_52 "PC给DCDC的诊断报文字节6";
CM_ SG_ 2148958068 P2D_BUCK_FUN_RX_Byte8_52 "PC给DCDC的诊断报文字节7";
CM_ SG_ 2148958069 P2D_BUCK_FUN_RX_Byte1_53 "PC给DCDC的诊断报文字节0";
CM_ SG_ 2148958069 P2D_BUCK_FUN_RX_Byte2_53 "PC给DCDC的诊断报文字节1";
CM_ SG_ 2148958069 P2D_BUCK_FUN_RX_Byte3_53 "PC给DCDC的诊断报文字节2";
CM_ SG_ 2148958069 P2D_BUCK_FUN_RX_Byte4_53 "PC给DCDC的诊断报文字节3";
CM_ SG_ 2148958069 P2D_BUCK_FUN_RX_Byte5_53 "PC给DCDC的诊断报文字节4";
CM_ SG_ 2148958069 P2D_BUCK_FUN_RX_Byte6_53 "PC给DCDC的诊断报文字节5";
CM_ SG_ 2148958069 P2D_BUCK_FUN_RX_Byte7_53 "PC给DCDC的诊断报文字节6";
CM_ SG_ 2148958069 P2D_BUCK_FUN_RX_Byte8_53 "PC给DCDC的诊断报文字节7";
CM_ SG_ 2148958070 P2D_BUCK_FUN_RX_Byte1_54 "PC给DCDC的诊断报文字节0";
CM_ SG_ 2148958070 P2D_BUCK_FUN_RX_Byte2_54 "PC给DCDC的诊断报文字节1";
CM_ SG_ 2148958070 P2D_BUCK_FUN_RX_Byte3_54 "PC给DCDC的诊断报文字节2";
CM_ SG_ 2148958070 P2D_BUCK_FUN_RX_Byte4_54 "PC给DCDC的诊断报文字节3";
CM_ SG_ 2148958070 P2D_BUCK_FUN_RX_Byte5_54 "PC给DCDC的诊断报文字节4";
CM_ SG_ 2148958070 P2D_BUCK_FUN_RX_Byte6_54 "PC给DCDC的诊断报文字节5";
CM_ SG_ 2148958070 P2D_BUCK_FUN_RX_Byte7_54 "PC给DCDC的诊断报文字节6";
CM_ SG_ 2148958070 P2D_BUCK_FUN_RX_Byte8_54 "PC给DCDC的诊断报文字节7";
CM_ SG_ 2148958071 P2D_BUCK_FUN_RX_Byte1_55 "PC给DCDC的诊断报文字节0";
CM_ SG_ 2148958071 P2D_BUCK_FUN_RX_Byte2_55 "PC给DCDC的诊断报文字节1";
CM_ SG_ 2148958071 P2D_BUCK_FUN_RX_Byte3_55 "PC给DCDC的诊断报文字节2";
CM_ SG_ 2148958071 P2D_BUCK_FUN_RX_Byte4_55 "PC给DCDC的诊断报文字节3";
CM_ SG_ 2148958071 P2D_BUCK_FUN_RX_Byte5_55 "PC给DCDC的诊断报文字节4";
CM_ SG_ 2148958071 P2D_BUCK_FUN_RX_Byte6_55 "PC给DCDC的诊断报文字节5";
CM_ SG_ 2148958071 P2D_BUCK_FUN_RX_Byte7_55 "PC给DCDC的诊断报文字节6";
CM_ SG_ 2148958071 P2D_BUCK_FUN_RX_Byte8_55 "PC给DCDC的诊断报文字节7";
CM_ SG_ 2148958072 P2D_BUCK_FUN_RX_Byte1_56 "PC给DCDC的诊断报文字节0";
CM_ SG_ 2148958072 P2D_BUCK_FUN_RX_Byte2_56 "PC给DCDC的诊断报文字节1";
CM_ SG_ 2148958072 P2D_BUCK_FUN_RX_Byte3_56 "PC给DCDC的诊断报文字节2";
CM_ SG_ 2148958072 P2D_BUCK_FUN_RX_Byte4_56 "PC给DCDC的诊断报文字节3";
CM_ SG_ 2148958072 P2D_BUCK_FUN_RX_Byte5_56 "PC给DCDC的诊断报文字节4";
CM_ SG_ 2148958072 P2D_BUCK_FUN_RX_Byte6_56 "PC给DCDC的诊断报文字节5";
CM_ SG_ 2148958072 P2D_BUCK_FUN_RX_Byte7_56 "PC给DCDC的诊断报文字节6";
CM_ SG_ 2148958072 P2D_BUCK_FUN_RX_Byte8_56 "PC给DCDC的诊断报文字节7";
CM_ SG_ 2148958073 P2D_BUCK_FUN_RX_Byte1_57 "PC给DCDC的诊断报文字节0";
CM_ SG_ 2148958073 P2D_BUCK_FUN_RX_Byte2_57 "PC给DCDC的诊断报文字节1";
CM_ SG_ 2148958073 P2D_BUCK_FUN_RX_Byte3_57 "PC给DCDC的诊断报文字节2";
CM_ SG_ 2148958073 P2D_BUCK_FUN_RX_Byte4_57 "PC给DCDC的诊断报文字节3";
CM_ SG_ 2148958073 P2D_BUCK_FUN_RX_Byte5_57 "PC给DCDC的诊断报文字节4";
CM_ SG_ 2148958073 P2D_BUCK_FUN_RX_Byte6_57 "PC给DCDC的诊断报文字节5";
CM_ SG_ 2148958073 P2D_BUCK_FUN_RX_Byte7_57 "PC给DCDC的诊断报文字节6";
CM_ SG_ 2148958073 P2D_BUCK_FUN_RX_Byte8_57 "PC给DCDC的诊断报文字节7";
CM_ SG_ 2148958074 P2D_BUCK_FUN_RX_Byte1_58 "PC给DCDC的诊断报文字节0";
CM_ SG_ 2148958074 P2D_BUCK_FUN_RX_Byte2_58 "PC给DCDC的诊断报文字节1";
CM_ SG_ 2148958074 P2D_BUCK_FUN_RX_Byte3_58 "PC给DCDC的诊断报文字节2";
CM_ SG_ 2148958074 P2D_BUCK_FUN_RX_Byte4_58 "PC给DCDC的诊断报文字节3";
CM_ SG_ 2148958074 P2D_BUCK_FUN_RX_Byte5_58 "PC给DCDC的诊断报文字节4";
CM_ SG_ 2148958074 P2D_BUCK_FUN_RX_Byte6_58 "PC给DCDC的诊断报文字节5";
CM_ SG_ 2148958074 P2D_BUCK_FUN_RX_Byte7_58 "PC给DCDC的诊断报文字节6";
CM_ SG_ 2148958074 P2D_BUCK_FUN_RX_Byte8_58 "PC给DCDC的诊断报文字节7";
CM_ SG_ 2148958075 P2D_BUCK_FUN_RX_Byte1_59 "PC给DCDC的诊断报文字节0";
CM_ SG_ 2148958075 P2D_BUCK_FUN_RX_Byte2_59 "PC给DCDC的诊断报文字节1";
CM_ SG_ 2148958075 P2D_BUCK_FUN_RX_Byte3_59 "PC给DCDC的诊断报文字节2";
CM_ SG_ 2148958075 P2D_BUCK_FUN_RX_Byte4_59 "PC给DCDC的诊断报文字节3";
CM_ SG_ 2148958075 P2D_BUCK_FUN_RX_Byte5_59 "PC给DCDC的诊断报文字节4";
CM_ SG_ 2148958075 P2D_BUCK_FUN_RX_Byte6_59 "PC给DCDC的诊断报文字节5";
CM_ SG_ 2148958075 P2D_BUCK_FUN_RX_Byte7_59 "PC给DCDC的诊断报文字节6";
CM_ SG_ 2148958075 P2D_BUCK_FUN_RX_Byte8_59 "PC给DCDC的诊断报文字节7";
CM_ SG_ 2148958076 P2D_BUCK_FUN_RX_Byte1_60 "PC给DCDC的诊断报文字节0";
CM_ SG_ 2148958076 P2D_BUCK_FUN_RX_Byte2_60 "PC给DCDC的诊断报文字节1";
CM_ SG_ 2148958076 P2D_BUCK_FUN_RX_Byte3_60 "PC给DCDC的诊断报文字节2";
CM_ SG_ 2148958076 P2D_BUCK_FUN_RX_Byte4_60 "PC给DCDC的诊断报文字节3";
CM_ SG_ 2148958076 P2D_BUCK_FUN_RX_Byte5_60 "PC给DCDC的诊断报文字节4";
CM_ SG_ 2148958076 P2D_BUCK_FUN_RX_Byte6_60 "PC给DCDC的诊断报文字节5";
CM_ SG_ 2148958076 P2D_BUCK_FUN_RX_Byte7_60 "PC给DCDC的诊断报文字节6";
CM_ SG_ 2148958076 P2D_BUCK_FUN_RX_Byte8_60 "PC给DCDC的诊断报文字节7";
CM_ SG_ 2148958077 P2D_BUCK_FUN_RX_Byte1_61 "PC给DCDC的诊断报文字节0";
CM_ SG_ 2148958077 P2D_BUCK_FUN_RX_Byte2_61 "PC给DCDC的诊断报文字节1";
CM_ SG_ 2148958077 P2D_BUCK_FUN_RX_Byte3_61 "PC给DCDC的诊断报文字节2";
CM_ SG_ 2148958077 P2D_BUCK_FUN_RX_Byte4_61 "PC给DCDC的诊断报文字节3";
CM_ SG_ 2148958077 P2D_BUCK_FUN_RX_Byte5_61 "PC给DCDC的诊断报文字节4";
CM_ SG_ 2148958077 P2D_BUCK_FUN_RX_Byte6_61 "PC给DCDC的诊断报文字节5";
CM_ SG_ 2148958077 P2D_BUCK_FUN_RX_Byte7_61 "PC给DCDC的诊断报文字节6";
CM_ SG_ 2148958077 P2D_BUCK_FUN_RX_Byte8_61 "PC给DCDC的诊断报文字节7";
CM_ SG_ 2148958078 P2D_BUCK_FUN_RX_Byte1_62 "PC给DCDC的诊断报文字节0";
CM_ SG_ 2148958078 P2D_BUCK_FUN_RX_Byte2_62 "PC给DCDC的诊断报文字节1";
CM_ SG_ 2148958078 P2D_BUCK_FUN_RX_Byte3_62 "PC给DCDC的诊断报文字节2";
CM_ SG_ 2148958078 P2D_BUCK_FUN_RX_Byte4_62 "PC给DCDC的诊断报文字节3";
CM_ SG_ 2148958078 P2D_BUCK_FUN_RX_Byte5_62 "PC给DCDC的诊断报文字节4";
CM_ SG_ 2148958078 P2D_BUCK_FUN_RX_Byte6_62 "PC给DCDC的诊断报文字节5";
CM_ SG_ 2148958078 P2D_BUCK_FUN_RX_Byte7_62 "PC给DCDC的诊断报文字节6";
CM_ SG_ 2148958078 P2D_BUCK_FUN_RX_Byte8_62 "PC给DCDC的诊断报文字节7";
CM_ SG_ 2148958079 P2D_BUCK_FUN_RX_Byte1_63 "PC给DCDC的诊断报文字节0";
CM_ SG_ 2148958079 P2D_BUCK_FUN_RX_Byte2_63 "PC给DCDC的诊断报文字节1";
CM_ SG_ 2148958079 P2D_BUCK_FUN_RX_Byte3_63 "PC给DCDC的诊断报文字节2";
CM_ SG_ 2148958079 P2D_BUCK_FUN_RX_Byte4_63 "PC给DCDC的诊断报文字节3";
CM_ SG_ 2148958079 P2D_BUCK_FUN_RX_Byte5_63 "PC给DCDC的诊断报文字节4";
CM_ SG_ 2148958079 P2D_BUCK_FUN_RX_Byte6_63 "PC给DCDC的诊断报文字节5";
CM_ SG_ 2148958079 P2D_BUCK_FUN_RX_Byte7_63 "PC给DCDC的诊断报文字节6";
CM_ SG_ 2148958079 P2D_BUCK_FUN_RX_Byte8_63 "PC给DCDC的诊断报文字节7";
CM_ SG_ 2149023553 P2D_BUCK_PHY_RX_Byte1_01 "依据CAN下载协议";
CM_ SG_ 2149023553 P2D_BUCK_PHY_RX_Byte2_01 "依据CAN下载协议";
CM_ SG_ 2149023553 P2D_BUCK_PHY_RX_Byte3_01 "依据CAN下载协议";
CM_ SG_ 2149023553 P2D_BUCK_PHY_RX_Byte4_01 "依据CAN下载协议";
CM_ SG_ 2149023553 P2D_BUCK_PHY_RX_Byte5_01 "依据CAN下载协议";
CM_ SG_ 2149023553 P2D_BUCK_PHY_RX_Byte6_01 "依据CAN下载协议";
CM_ SG_ 2149023553 P2D_BUCK_PHY_RX_Byte7_01 "依据CAN下载协议";
CM_ SG_ 2149023553 P2D_BUCK_PHY_RX_Byte8_01 "依据CAN下载协议";
CM_ SG_ 2149023554 P2D_BUCK_PHY_RX_Byte1_02 "依据CAN下载协议";
CM_ SG_ 2149023554 P2D_BUCK_PHY_RX_Byte2_02 "依据CAN下载协议";
CM_ SG_ 2149023554 P2D_BUCK_PHY_RX_Byte3_02 "依据CAN下载协议";
CM_ SG_ 2149023554 P2D_BUCK_PHY_RX_Byte4_02 "依据CAN下载协议";
CM_ SG_ 2149023554 P2D_BUCK_PHY_RX_Byte5_02 "依据CAN下载协议";
CM_ SG_ 2149023554 P2D_BUCK_PHY_RX_Byte6_02 "依据CAN下载协议";
CM_ SG_ 2149023554 P2D_BUCK_PHY_RX_Byte7_02 "依据CAN下载协议";
CM_ SG_ 2149023554 P2D_BUCK_PHY_RX_Byte8_02 "依据CAN下载协议";
CM_ SG_ 2149023555 P2D_BUCK_PHY_RX_Byte1_03 "依据CAN下载协议";
CM_ SG_ 2149023555 P2D_BUCK_PHY_RX_Byte2_03 "依据CAN下载协议";
CM_ SG_ 2149023555 P2D_BUCK_PHY_RX_Byte3_03 "依据CAN下载协议";
CM_ SG_ 2149023555 P2D_BUCK_PHY_RX_Byte4_03 "依据CAN下载协议";
CM_ SG_ 2149023555 P2D_BUCK_PHY_RX_Byte5_03 "依据CAN下载协议";
CM_ SG_ 2149023555 P2D_BUCK_PHY_RX_Byte6_03 "依据CAN下载协议";
CM_ SG_ 2149023555 P2D_BUCK_PHY_RX_Byte7_03 "依据CAN下载协议";
CM_ SG_ 2149023555 P2D_BUCK_PHY_RX_Byte8_03 "依据CAN下载协议";
CM_ SG_ 2149023556 P2D_BUCK_PHY_RX_Byte1_04 "依据CAN下载协议";
CM_ SG_ 2149023556 P2D_BUCK_PHY_RX_Byte2_04 "依据CAN下载协议";
CM_ SG_ 2149023556 P2D_BUCK_PHY_RX_Byte3_04 "依据CAN下载协议";
CM_ SG_ 2149023556 P2D_BUCK_PHY_RX_Byte4_04 "依据CAN下载协议";
CM_ SG_ 2149023556 P2D_BUCK_PHY_RX_Byte5_04 "依据CAN下载协议";
CM_ SG_ 2149023556 P2D_BUCK_PHY_RX_Byte6_04 "依据CAN下载协议";
CM_ SG_ 2149023556 P2D_BUCK_PHY_RX_Byte7_04 "依据CAN下载协议";
CM_ SG_ 2149023556 P2D_BUCK_PHY_RX_Byte8_04 "依据CAN下载协议";
CM_ SG_ 2149023557 P2D_BUCK_PHY_RX_Byte1_05 "依据CAN下载协议";
CM_ SG_ 2149023557 P2D_BUCK_PHY_RX_Byte2_05 "依据CAN下载协议";
CM_ SG_ 2149023557 P2D_BUCK_PHY_RX_Byte3_05 "依据CAN下载协议";
CM_ SG_ 2149023557 P2D_BUCK_PHY_RX_Byte4_05 "依据CAN下载协议";
CM_ SG_ 2149023557 P2D_BUCK_PHY_RX_Byte5_05 "依据CAN下载协议";
CM_ SG_ 2149023557 P2D_BUCK_PHY_RX_Byte6_05 "依据CAN下载协议";
CM_ SG_ 2149023557 P2D_BUCK_PHY_RX_Byte7_05 "依据CAN下载协议";
CM_ SG_ 2149023557 P2D_BUCK_PHY_RX_Byte8_05 "依据CAN下载协议";
CM_ SG_ 2149023558 P2D_BUCK_PHY_RX_Byte1_06 "依据CAN下载协议";
CM_ SG_ 2149023558 P2D_BUCK_PHY_RX_Byte2_06 "依据CAN下载协议";
CM_ SG_ 2149023558 P2D_BUCK_PHY_RX_Byte3_06 "依据CAN下载协议";
CM_ SG_ 2149023558 P2D_BUCK_PHY_RX_Byte4_06 "依据CAN下载协议";
CM_ SG_ 2149023558 P2D_BUCK_PHY_RX_Byte5_06 "依据CAN下载协议";
CM_ SG_ 2149023558 P2D_BUCK_PHY_RX_Byte6_06 "依据CAN下载协议";
CM_ SG_ 2149023558 P2D_BUCK_PHY_RX_Byte7_06 "依据CAN下载协议";
CM_ SG_ 2149023558 P2D_BUCK_PHY_RX_Byte8_06 "依据CAN下载协议";
CM_ SG_ 2149023559 P2D_BUCK_PHY_RX_Byte1_07 "依据CAN下载协议";
CM_ SG_ 2149023559 P2D_BUCK_PHY_RX_Byte2_07 "依据CAN下载协议";
CM_ SG_ 2149023559 P2D_BUCK_PHY_RX_Byte3_07 "依据CAN下载协议";
CM_ SG_ 2149023559 P2D_BUCK_PHY_RX_Byte4_07 "依据CAN下载协议";
CM_ SG_ 2149023559 P2D_BUCK_PHY_RX_Byte5_07 "依据CAN下载协议";
CM_ SG_ 2149023559 P2D_BUCK_PHY_RX_Byte6_07 "依据CAN下载协议";
CM_ SG_ 2149023559 P2D_BUCK_PHY_RX_Byte7_07 "依据CAN下载协议";
CM_ SG_ 2149023559 P2D_BUCK_PHY_RX_Byte8_07 "依据CAN下载协议";
CM_ SG_ 2149023560 P2D_BUCK_PHY_RX_Byte1_08 "依据CAN下载协议";
CM_ SG_ 2149023560 P2D_BUCK_PHY_RX_Byte2_08 "依据CAN下载协议";
CM_ SG_ 2149023560 P2D_BUCK_PHY_RX_Byte3_08 "依据CAN下载协议";
CM_ SG_ 2149023560 P2D_BUCK_PHY_RX_Byte4_08 "依据CAN下载协议";
CM_ SG_ 2149023560 P2D_BUCK_PHY_RX_Byte5_08 "依据CAN下载协议";
CM_ SG_ 2149023560 P2D_BUCK_PHY_RX_Byte6_08 "依据CAN下载协议";
CM_ SG_ 2149023560 P2D_BUCK_PHY_RX_Byte7_08 "依据CAN下载协议";
CM_ SG_ 2149023560 P2D_BUCK_PHY_RX_Byte8_08 "依据CAN下载协议";
CM_ SG_ 2149023561 P2D_BUCK_PHY_RX_Byte1_09 "依据CAN下载协议";
CM_ SG_ 2149023561 P2D_BUCK_PHY_RX_Byte2_09 "依据CAN下载协议";
CM_ SG_ 2149023561 P2D_BUCK_PHY_RX_Byte3_09 "依据CAN下载协议";
CM_ SG_ 2149023561 P2D_BUCK_PHY_RX_Byte4_09 "依据CAN下载协议";
CM_ SG_ 2149023561 P2D_BUCK_PHY_RX_Byte5_09 "依据CAN下载协议";
CM_ SG_ 2149023561 P2D_BUCK_PHY_RX_Byte6_09 "依据CAN下载协议";
CM_ SG_ 2149023561 P2D_BUCK_PHY_RX_Byte7_09 "依据CAN下载协议";
CM_ SG_ 2149023561 P2D_BUCK_PHY_RX_Byte8_09 "依据CAN下载协议";
CM_ SG_ 2149023562 P2D_BUCK_PHY_RX_Byte1_10 "依据CAN下载协议";
CM_ SG_ 2149023562 P2D_BUCK_PHY_RX_Byte2_10 "依据CAN下载协议";
CM_ SG_ 2149023562 P2D_BUCK_PHY_RX_Byte3_10 "依据CAN下载协议";
CM_ SG_ 2149023562 P2D_BUCK_PHY_RX_Byte4_10 "依据CAN下载协议";
CM_ SG_ 2149023562 P2D_BUCK_PHY_RX_Byte5_10 "依据CAN下载协议";
CM_ SG_ 2149023562 P2D_BUCK_PHY_RX_Byte6_10 "依据CAN下载协议";
CM_ SG_ 2149023562 P2D_BUCK_PHY_RX_Byte7_10 "依据CAN下载协议";
CM_ SG_ 2149023562 P2D_BUCK_PHY_RX_Byte8_10 "依据CAN下载协议";
CM_ SG_ 2149023563 P2D_BUCK_PHY_RX_Byte1_11 "依据CAN下载协议";
CM_ SG_ 2149023563 P2D_BUCK_PHY_RX_Byte2_11 "依据CAN下载协议";
CM_ SG_ 2149023563 P2D_BUCK_PHY_RX_Byte3_11 "依据CAN下载协议";
CM_ SG_ 2149023563 P2D_BUCK_PHY_RX_Byte4_11 "依据CAN下载协议";
CM_ SG_ 2149023563 P2D_BUCK_PHY_RX_Byte5_11 "依据CAN下载协议";
CM_ SG_ 2149023563 P2D_BUCK_PHY_RX_Byte6_11 "依据CAN下载协议";
CM_ SG_ 2149023563 P2D_BUCK_PHY_RX_Byte7_11 "依据CAN下载协议";
CM_ SG_ 2149023563 P2D_BUCK_PHY_RX_Byte8_11 "依据CAN下载协议";
CM_ SG_ 2149023564 P2D_BUCK_PHY_RX_Byte1_12 "依据CAN下载协议";
CM_ SG_ 2149023564 P2D_BUCK_PHY_RX_Byte2_12 "依据CAN下载协议";
CM_ SG_ 2149023564 P2D_BUCK_PHY_RX_Byte3_12 "依据CAN下载协议";
CM_ SG_ 2149023564 P2D_BUCK_PHY_RX_Byte4_12 "依据CAN下载协议";
CM_ SG_ 2149023564 P2D_BUCK_PHY_RX_Byte5_12 "依据CAN下载协议";
CM_ SG_ 2149023564 P2D_BUCK_PHY_RX_Byte6_12 "依据CAN下载协议";
CM_ SG_ 2149023564 P2D_BUCK_PHY_RX_Byte7_12 "依据CAN下载协议";
CM_ SG_ 2149023564 P2D_BUCK_PHY_RX_Byte8_12 "依据CAN下载协议";
CM_ SG_ 2149023565 P2D_BUCK_PHY_RX_Byte1_13 "依据CAN下载协议";
CM_ SG_ 2149023565 P2D_BUCK_PHY_RX_Byte2_13 "依据CAN下载协议";
CM_ SG_ 2149023565 P2D_BUCK_PHY_RX_Byte3_13 "依据CAN下载协议";
CM_ SG_ 2149023565 P2D_BUCK_PHY_RX_Byte4_13 "依据CAN下载协议";
CM_ SG_ 2149023565 P2D_BUCK_PHY_RX_Byte5_13 "依据CAN下载协议";
CM_ SG_ 2149023565 P2D_BUCK_PHY_RX_Byte6_13 "依据CAN下载协议";
CM_ SG_ 2149023565 P2D_BUCK_PHY_RX_Byte7_13 "依据CAN下载协议";
CM_ SG_ 2149023565 P2D_BUCK_PHY_RX_Byte8_13 "依据CAN下载协议";
CM_ SG_ 2149023566 P2D_BUCK_PHY_RX_Byte1_14 "依据CAN下载协议";
CM_ SG_ 2149023566 P2D_BUCK_PHY_RX_Byte2_14 "依据CAN下载协议";
CM_ SG_ 2149023566 P2D_BUCK_PHY_RX_Byte3_14 "依据CAN下载协议";
CM_ SG_ 2149023566 P2D_BUCK_PHY_RX_Byte4_14 "依据CAN下载协议";
CM_ SG_ 2149023566 P2D_BUCK_PHY_RX_Byte5_14 "依据CAN下载协议";
CM_ SG_ 2149023566 P2D_BUCK_PHY_RX_Byte6_14 "依据CAN下载协议";
CM_ SG_ 2149023566 P2D_BUCK_PHY_RX_Byte7_14 "依据CAN下载协议";
CM_ SG_ 2149023566 P2D_BUCK_PHY_RX_Byte8_14 "依据CAN下载协议";
CM_ SG_ 2149023567 P2D_BUCK_PHY_RX_Byte1_15 "依据CAN下载协议";
CM_ SG_ 2149023567 P2D_BUCK_PHY_RX_Byte2_15 "依据CAN下载协议";
CM_ SG_ 2149023567 P2D_BUCK_PHY_RX_Byte3_15 "依据CAN下载协议";
CM_ SG_ 2149023567 P2D_BUCK_PHY_RX_Byte4_15 "依据CAN下载协议";
CM_ SG_ 2149023567 P2D_BUCK_PHY_RX_Byte5_15 "依据CAN下载协议";
CM_ SG_ 2149023567 P2D_BUCK_PHY_RX_Byte6_15 "依据CAN下载协议";
CM_ SG_ 2149023567 P2D_BUCK_PHY_RX_Byte7_15 "依据CAN下载协议";
CM_ SG_ 2149023567 P2D_BUCK_PHY_RX_Byte8_15 "依据CAN下载协议";
CM_ SG_ 2149023568 P2D_BUCK_PHY_RX_Byte1_16 "依据CAN下载协议";
CM_ SG_ 2149023568 P2D_BUCK_PHY_RX_Byte2_16 "依据CAN下载协议";
CM_ SG_ 2149023568 P2D_BUCK_PHY_RX_Byte3_16 "依据CAN下载协议";
CM_ SG_ 2149023568 P2D_BUCK_PHY_RX_Byte4_16 "依据CAN下载协议";
CM_ SG_ 2149023568 P2D_BUCK_PHY_RX_Byte5_16 "依据CAN下载协议";
CM_ SG_ 2149023568 P2D_BUCK_PHY_RX_Byte6_16 "依据CAN下载协议";
CM_ SG_ 2149023568 P2D_BUCK_PHY_RX_Byte7_16 "依据CAN下载协议";
CM_ SG_ 2149023568 P2D_BUCK_PHY_RX_Byte8_16 "依据CAN下载协议";
CM_ SG_ 2149023569 P2D_BUCK_PHY_RX_Byte1_17 "依据CAN下载协议";
CM_ SG_ 2149023569 P2D_BUCK_PHY_RX_Byte2_17 "依据CAN下载协议";
CM_ SG_ 2149023569 P2D_BUCK_PHY_RX_Byte3_17 "依据CAN下载协议";
CM_ SG_ 2149023569 P2D_BUCK_PHY_RX_Byte4_17 "依据CAN下载协议";
CM_ SG_ 2149023569 P2D_BUCK_PHY_RX_Byte5_17 "依据CAN下载协议";
CM_ SG_ 2149023569 P2D_BUCK_PHY_RX_Byte6_17 "依据CAN下载协议";
CM_ SG_ 2149023569 P2D_BUCK_PHY_RX_Byte7_17 "依据CAN下载协议";
CM_ SG_ 2149023569 P2D_BUCK_PHY_RX_Byte8_17 "依据CAN下载协议";
CM_ SG_ 2149023570 P2D_BUCK_PHY_RX_Byte1_18 "依据CAN下载协议";
CM_ SG_ 2149023570 P2D_BUCK_PHY_RX_Byte2_18 "依据CAN下载协议";
CM_ SG_ 2149023570 P2D_BUCK_PHY_RX_Byte3_18 "依据CAN下载协议";
CM_ SG_ 2149023570 P2D_BUCK_PHY_RX_Byte4_18 "依据CAN下载协议";
CM_ SG_ 2149023570 P2D_BUCK_PHY_RX_Byte5_18 "依据CAN下载协议";
CM_ SG_ 2149023570 P2D_BUCK_PHY_RX_Byte6_18 "依据CAN下载协议";
CM_ SG_ 2149023570 P2D_BUCK_PHY_RX_Byte7_18 "依据CAN下载协议";
CM_ SG_ 2149023570 P2D_BUCK_PHY_RX_Byte8_18 "依据CAN下载协议";
CM_ SG_ 2149023571 P2D_BUCK_PHY_RX_Byte1_19 "依据CAN下载协议";
CM_ SG_ 2149023571 P2D_BUCK_PHY_RX_Byte2_19 "依据CAN下载协议";
CM_ SG_ 2149023571 P2D_BUCK_PHY_RX_Byte3_19 "依据CAN下载协议";
CM_ SG_ 2149023571 P2D_BUCK_PHY_RX_Byte4_19 "依据CAN下载协议";
CM_ SG_ 2149023571 P2D_BUCK_PHY_RX_Byte5_19 "依据CAN下载协议";
CM_ SG_ 2149023571 P2D_BUCK_PHY_RX_Byte6_19 "依据CAN下载协议";
CM_ SG_ 2149023571 P2D_BUCK_PHY_RX_Byte7_19 "依据CAN下载协议";
CM_ SG_ 2149023571 P2D_BUCK_PHY_RX_Byte8_19 "依据CAN下载协议";
CM_ SG_ 2149023572 P2D_BUCK_PHY_RX_Byte1_20 "依据CAN下载协议";
CM_ SG_ 2149023572 P2D_BUCK_PHY_RX_Byte2_20 "依据CAN下载协议";
CM_ SG_ 2149023572 P2D_BUCK_PHY_RX_Byte3_20 "依据CAN下载协议";
CM_ SG_ 2149023572 P2D_BUCK_PHY_RX_Byte4_20 "依据CAN下载协议";
CM_ SG_ 2149023572 P2D_BUCK_PHY_RX_Byte5_20 "依据CAN下载协议";
CM_ SG_ 2149023572 P2D_BUCK_PHY_RX_Byte6_20 "依据CAN下载协议";
CM_ SG_ 2149023572 P2D_BUCK_PHY_RX_Byte7_20 "依据CAN下载协议";
CM_ SG_ 2149023572 P2D_BUCK_PHY_RX_Byte8_20 "依据CAN下载协议";
CM_ SG_ 2149023573 P2D_BUCK_PHY_RX_Byte1_21 "依据CAN下载协议";
CM_ SG_ 2149023573 P2D_BUCK_PHY_RX_Byte2_21 "依据CAN下载协议";
CM_ SG_ 2149023573 P2D_BUCK_PHY_RX_Byte3_21 "依据CAN下载协议";
CM_ SG_ 2149023573 P2D_BUCK_PHY_RX_Byte4_21 "依据CAN下载协议";
CM_ SG_ 2149023573 P2D_BUCK_PHY_RX_Byte5_21 "依据CAN下载协议";
CM_ SG_ 2149023573 P2D_BUCK_PHY_RX_Byte6_21 "依据CAN下载协议";
CM_ SG_ 2149023573 P2D_BUCK_PHY_RX_Byte7_21 "依据CAN下载协议";
CM_ SG_ 2149023573 P2D_BUCK_PHY_RX_Byte8_21 "依据CAN下载协议";
CM_ SG_ 2149023574 P2D_BUCK_PHY_RX_Byte1_22 "依据CAN下载协议";
CM_ SG_ 2149023574 P2D_BUCK_PHY_RX_Byte2_22 "依据CAN下载协议";
CM_ SG_ 2149023574 P2D_BUCK_PHY_RX_Byte3_22 "依据CAN下载协议";
CM_ SG_ 2149023574 P2D_BUCK_PHY_RX_Byte4_22 "依据CAN下载协议";
CM_ SG_ 2149023574 P2D_BUCK_PHY_RX_Byte5_22 "依据CAN下载协议";
CM_ SG_ 2149023574 P2D_BUCK_PHY_RX_Byte6_22 "依据CAN下载协议";
CM_ SG_ 2149023574 P2D_BUCK_PHY_RX_Byte7_22 "依据CAN下载协议";
CM_ SG_ 2149023574 P2D_BUCK_PHY_RX_Byte8_22 "依据CAN下载协议";
CM_ SG_ 2149023575 P2D_BUCK_PHY_RX_Byte1_23 "依据CAN下载协议";
CM_ SG_ 2149023575 P2D_BUCK_PHY_RX_Byte2_23 "依据CAN下载协议";
CM_ SG_ 2149023575 P2D_BUCK_PHY_RX_Byte3_23 "依据CAN下载协议";
CM_ SG_ 2149023575 P2D_BUCK_PHY_RX_Byte4_23 "依据CAN下载协议";
CM_ SG_ 2149023575 P2D_BUCK_PHY_RX_Byte5_23 "依据CAN下载协议";
CM_ SG_ 2149023575 P2D_BUCK_PHY_RX_Byte6_23 "依据CAN下载协议";
CM_ SG_ 2149023575 P2D_BUCK_PHY_RX_Byte7_23 "依据CAN下载协议";
CM_ SG_ 2149023575 P2D_BUCK_PHY_RX_Byte8_23 "依据CAN下载协议";
CM_ SG_ 2149023576 P2D_BUCK_PHY_RX_Byte1_24 "依据CAN下载协议";
CM_ SG_ 2149023576 P2D_BUCK_PHY_RX_Byte2_24 "依据CAN下载协议";
CM_ SG_ 2149023576 P2D_BUCK_PHY_RX_Byte3_24 "依据CAN下载协议";
CM_ SG_ 2149023576 P2D_BUCK_PHY_RX_Byte4_24 "依据CAN下载协议";
CM_ SG_ 2149023576 P2D_BUCK_PHY_RX_Byte5_24 "依据CAN下载协议";
CM_ SG_ 2149023576 P2D_BUCK_PHY_RX_Byte6_24 "依据CAN下载协议";
CM_ SG_ 2149023576 P2D_BUCK_PHY_RX_Byte7_24 "依据CAN下载协议";
CM_ SG_ 2149023576 P2D_BUCK_PHY_RX_Byte8_24 "依据CAN下载协议";
CM_ SG_ 2149023577 P2D_BUCK_PHY_RX_Byte1_25 "依据CAN下载协议";
CM_ SG_ 2149023577 P2D_BUCK_PHY_RX_Byte2_25 "依据CAN下载协议";
CM_ SG_ 2149023577 P2D_BUCK_PHY_RX_Byte3_25 "依据CAN下载协议";
CM_ SG_ 2149023577 P2D_BUCK_PHY_RX_Byte4_25 "依据CAN下载协议";
CM_ SG_ 2149023577 P2D_BUCK_PHY_RX_Byte5_25 "依据CAN下载协议";
CM_ SG_ 2149023577 P2D_BUCK_PHY_RX_Byte6_25 "依据CAN下载协议";
CM_ SG_ 2149023577 P2D_BUCK_PHY_RX_Byte7_25 "依据CAN下载协议";
CM_ SG_ 2149023577 P2D_BUCK_PHY_RX_Byte8_25 "依据CAN下载协议";
CM_ SG_ 2149023578 P2D_BUCK_PHY_RX_Byte1_26 "依据CAN下载协议";
CM_ SG_ 2149023578 P2D_BUCK_PHY_RX_Byte2_26 "依据CAN下载协议";
CM_ SG_ 2149023578 P2D_BUCK_PHY_RX_Byte3_26 "依据CAN下载协议";
CM_ SG_ 2149023578 P2D_BUCK_PHY_RX_Byte4_26 "依据CAN下载协议";
CM_ SG_ 2149023578 P2D_BUCK_PHY_RX_Byte5_26 "依据CAN下载协议";
CM_ SG_ 2149023578 P2D_BUCK_PHY_RX_Byte6_26 "依据CAN下载协议";
CM_ SG_ 2149023578 P2D_BUCK_PHY_RX_Byte7_26 "依据CAN下载协议";
CM_ SG_ 2149023578 P2D_BUCK_PHY_RX_Byte8_26 "依据CAN下载协议";
CM_ SG_ 2149023579 P2D_BUCK_PHY_RX_Byte1_27 "依据CAN下载协议";
CM_ SG_ 2149023579 P2D_BUCK_PHY_RX_Byte2_27 "依据CAN下载协议";
CM_ SG_ 2149023579 P2D_BUCK_PHY_RX_Byte3_27 "依据CAN下载协议";
CM_ SG_ 2149023579 P2D_BUCK_PHY_RX_Byte4_27 "依据CAN下载协议";
CM_ SG_ 2149023579 P2D_BUCK_PHY_RX_Byte5_27 "依据CAN下载协议";
CM_ SG_ 2149023579 P2D_BUCK_PHY_RX_Byte6_27 "依据CAN下载协议";
CM_ SG_ 2149023579 P2D_BUCK_PHY_RX_Byte7_27 "依据CAN下载协议";
CM_ SG_ 2149023579 P2D_BUCK_PHY_RX_Byte8_27 "依据CAN下载协议";
CM_ SG_ 2149023580 P2D_BUCK_PHY_RX_Byte1_28 "依据CAN下载协议";
CM_ SG_ 2149023580 P2D_BUCK_PHY_RX_Byte2_28 "依据CAN下载协议";
CM_ SG_ 2149023580 P2D_BUCK_PHY_RX_Byte3_28 "依据CAN下载协议";
CM_ SG_ 2149023580 P2D_BUCK_PHY_RX_Byte4_28 "依据CAN下载协议";
CM_ SG_ 2149023580 P2D_BUCK_PHY_RX_Byte5_28 "依据CAN下载协议";
CM_ SG_ 2149023580 P2D_BUCK_PHY_RX_Byte6_28 "依据CAN下载协议";
CM_ SG_ 2149023580 P2D_BUCK_PHY_RX_Byte7_28 "依据CAN下载协议";
CM_ SG_ 2149023580 P2D_BUCK_PHY_RX_Byte8_28 "依据CAN下载协议";
CM_ SG_ 2149023581 P2D_BUCK_PHY_RX_Byte1_29 "依据CAN下载协议";
CM_ SG_ 2149023581 P2D_BUCK_PHY_RX_Byte2_29 "依据CAN下载协议";
CM_ SG_ 2149023581 P2D_BUCK_PHY_RX_Byte3_29 "依据CAN下载协议";
CM_ SG_ 2149023581 P2D_BUCK_PHY_RX_Byte4_29 "依据CAN下载协议";
CM_ SG_ 2149023581 P2D_BUCK_PHY_RX_Byte5_29 "依据CAN下载协议";
CM_ SG_ 2149023581 P2D_BUCK_PHY_RX_Byte6_29 "依据CAN下载协议";
CM_ SG_ 2149023581 P2D_BUCK_PHY_RX_Byte7_29 "依据CAN下载协议";
CM_ SG_ 2149023581 P2D_BUCK_PHY_RX_Byte8_29 "依据CAN下载协议";
CM_ SG_ 2149023582 P2D_BUCK_PHY_RX_Byte1_30 "依据CAN下载协议";
CM_ SG_ 2149023582 P2D_BUCK_PHY_RX_Byte2_30 "依据CAN下载协议";
CM_ SG_ 2149023582 P2D_BUCK_PHY_RX_Byte3_30 "依据CAN下载协议";
CM_ SG_ 2149023582 P2D_BUCK_PHY_RX_Byte4_30 "依据CAN下载协议";
CM_ SG_ 2149023582 P2D_BUCK_PHY_RX_Byte5_30 "依据CAN下载协议";
CM_ SG_ 2149023582 P2D_BUCK_PHY_RX_Byte6_30 "依据CAN下载协议";
CM_ SG_ 2149023582 P2D_BUCK_PHY_RX_Byte7_30 "依据CAN下载协议";
CM_ SG_ 2149023582 P2D_BUCK_PHY_RX_Byte8_30 "依据CAN下载协议";
CM_ SG_ 2149023583 P2D_BUCK_PHY_RX_Byte1_31 "依据CAN下载协议";
CM_ SG_ 2149023583 P2D_BUCK_PHY_RX_Byte2_31 "依据CAN下载协议";
CM_ SG_ 2149023583 P2D_BUCK_PHY_RX_Byte3_31 "依据CAN下载协议";
CM_ SG_ 2149023583 P2D_BUCK_PHY_RX_Byte4_31 "依据CAN下载协议";
CM_ SG_ 2149023583 P2D_BUCK_PHY_RX_Byte5_31 "依据CAN下载协议";
CM_ SG_ 2149023583 P2D_BUCK_PHY_RX_Byte6_31 "依据CAN下载协议";
CM_ SG_ 2149023583 P2D_BUCK_PHY_RX_Byte7_31 "依据CAN下载协议";
CM_ SG_ 2149023583 P2D_BUCK_PHY_RX_Byte8_31 "依据CAN下载协议";
CM_ SG_ 2149023584 P2D_BUCK_PHY_RX_Byte1_32 "依据CAN下载协议";
CM_ SG_ 2149023584 P2D_BUCK_PHY_RX_Byte2_32 "依据CAN下载协议";
CM_ SG_ 2149023584 P2D_BUCK_PHY_RX_Byte3_32 "依据CAN下载协议";
CM_ SG_ 2149023584 P2D_BUCK_PHY_RX_Byte4_32 "依据CAN下载协议";
CM_ SG_ 2149023584 P2D_BUCK_PHY_RX_Byte5_32 "依据CAN下载协议";
CM_ SG_ 2149023584 P2D_BUCK_PHY_RX_Byte6_32 "依据CAN下载协议";
CM_ SG_ 2149023584 P2D_BUCK_PHY_RX_Byte7_32 "依据CAN下载协议";
CM_ SG_ 2149023584 P2D_BUCK_PHY_RX_Byte8_32 "依据CAN下载协议";
CM_ SG_ 2149023585 P2D_BUCK_PHY_RX_Byte1_33 "依据CAN下载协议";
CM_ SG_ 2149023585 P2D_BUCK_PHY_RX_Byte2_33 "依据CAN下载协议";
CM_ SG_ 2149023585 P2D_BUCK_PHY_RX_Byte3_33 "依据CAN下载协议";
CM_ SG_ 2149023585 P2D_BUCK_PHY_RX_Byte4_33 "依据CAN下载协议";
CM_ SG_ 2149023585 P2D_BUCK_PHY_RX_Byte5_33 "依据CAN下载协议";
CM_ SG_ 2149023585 P2D_BUCK_PHY_RX_Byte6_33 "依据CAN下载协议";
CM_ SG_ 2149023585 P2D_BUCK_PHY_RX_Byte7_33 "依据CAN下载协议";
CM_ SG_ 2149023585 P2D_BUCK_PHY_RX_Byte8_33 "依据CAN下载协议";
CM_ SG_ 2149023586 P2D_BUCK_PHY_RX_Byte1_34 "依据CAN下载协议";
CM_ SG_ 2149023586 P2D_BUCK_PHY_RX_Byte2_34 "依据CAN下载协议";
CM_ SG_ 2149023586 P2D_BUCK_PHY_RX_Byte3_34 "依据CAN下载协议";
CM_ SG_ 2149023586 P2D_BUCK_PHY_RX_Byte4_34 "依据CAN下载协议";
CM_ SG_ 2149023586 P2D_BUCK_PHY_RX_Byte5_34 "依据CAN下载协议";
CM_ SG_ 2149023586 P2D_BUCK_PHY_RX_Byte6_34 "依据CAN下载协议";
CM_ SG_ 2149023586 P2D_BUCK_PHY_RX_Byte7_34 "依据CAN下载协议";
CM_ SG_ 2149023586 P2D_BUCK_PHY_RX_Byte8_34 "依据CAN下载协议";
CM_ SG_ 2149023587 P2D_BUCK_PHY_RX_Byte1_35 "依据CAN下载协议";
CM_ SG_ 2149023587 P2D_BUCK_PHY_RX_Byte2_35 "依据CAN下载协议";
CM_ SG_ 2149023587 P2D_BUCK_PHY_RX_Byte3_35 "依据CAN下载协议";
CM_ SG_ 2149023587 P2D_BUCK_PHY_RX_Byte4_35 "依据CAN下载协议";
CM_ SG_ 2149023587 P2D_BUCK_PHY_RX_Byte5_35 "依据CAN下载协议";
CM_ SG_ 2149023587 P2D_BUCK_PHY_RX_Byte6_35 "依据CAN下载协议";
CM_ SG_ 2149023587 P2D_BUCK_PHY_RX_Byte7_35 "依据CAN下载协议";
CM_ SG_ 2149023587 P2D_BUCK_PHY_RX_Byte8_35 "依据CAN下载协议";
CM_ SG_ 2149023588 P2D_BUCK_PHY_RX_Byte1_36 "依据CAN下载协议";
CM_ SG_ 2149023588 P2D_BUCK_PHY_RX_Byte2_36 "依据CAN下载协议";
CM_ SG_ 2149023588 P2D_BUCK_PHY_RX_Byte3_36 "依据CAN下载协议";
CM_ SG_ 2149023588 P2D_BUCK_PHY_RX_Byte4_36 "依据CAN下载协议";
CM_ SG_ 2149023588 P2D_BUCK_PHY_RX_Byte5_36 "依据CAN下载协议";
CM_ SG_ 2149023588 P2D_BUCK_PHY_RX_Byte6_36 "依据CAN下载协议";
CM_ SG_ 2149023588 P2D_BUCK_PHY_RX_Byte7_36 "依据CAN下载协议";
CM_ SG_ 2149023588 P2D_BUCK_PHY_RX_Byte8_36 "依据CAN下载协议";
CM_ SG_ 2149023589 P2D_BUCK_PHY_RX_Byte1_37 "依据CAN下载协议";
CM_ SG_ 2149023589 P2D_BUCK_PHY_RX_Byte2_37 "依据CAN下载协议";
CM_ SG_ 2149023589 P2D_BUCK_PHY_RX_Byte3_37 "依据CAN下载协议";
CM_ SG_ 2149023589 P2D_BUCK_PHY_RX_Byte4_37 "依据CAN下载协议";
CM_ SG_ 2149023589 P2D_BUCK_PHY_RX_Byte5_37 "依据CAN下载协议";
CM_ SG_ 2149023589 P2D_BUCK_PHY_RX_Byte6_37 "依据CAN下载协议";
CM_ SG_ 2149023589 P2D_BUCK_PHY_RX_Byte7_37 "依据CAN下载协议";
CM_ SG_ 2149023589 P2D_BUCK_PHY_RX_Byte8_37 "依据CAN下载协议";
CM_ SG_ 2149023590 P2D_BUCK_PHY_RX_Byte1_38 "依据CAN下载协议";
CM_ SG_ 2149023590 P2D_BUCK_PHY_RX_Byte2_38 "依据CAN下载协议";
CM_ SG_ 2149023590 P2D_BUCK_PHY_RX_Byte3_38 "依据CAN下载协议";
CM_ SG_ 2149023590 P2D_BUCK_PHY_RX_Byte4_38 "依据CAN下载协议";
CM_ SG_ 2149023590 P2D_BUCK_PHY_RX_Byte5_38 "依据CAN下载协议";
CM_ SG_ 2149023590 P2D_BUCK_PHY_RX_Byte6_38 "依据CAN下载协议";
CM_ SG_ 2149023590 P2D_BUCK_PHY_RX_Byte7_38 "依据CAN下载协议";
CM_ SG_ 2149023590 P2D_BUCK_PHY_RX_Byte8_38 "依据CAN下载协议";
CM_ SG_ 2149023591 P2D_BUCK_PHY_RX_Byte1_39 "依据CAN下载协议";
CM_ SG_ 2149023591 P2D_BUCK_PHY_RX_Byte2_39 "依据CAN下载协议";
CM_ SG_ 2149023591 P2D_BUCK_PHY_RX_Byte3_39 "依据CAN下载协议";
CM_ SG_ 2149023591 P2D_BUCK_PHY_RX_Byte4_39 "依据CAN下载协议";
CM_ SG_ 2149023591 P2D_BUCK_PHY_RX_Byte5_39 "依据CAN下载协议";
CM_ SG_ 2149023591 P2D_BUCK_PHY_RX_Byte6_39 "依据CAN下载协议";
CM_ SG_ 2149023591 P2D_BUCK_PHY_RX_Byte7_39 "依据CAN下载协议";
CM_ SG_ 2149023591 P2D_BUCK_PHY_RX_Byte8_39 "依据CAN下载协议";
CM_ SG_ 2149023592 P2D_BUCK_PHY_RX_Byte1_40 "依据CAN下载协议";
CM_ SG_ 2149023592 P2D_BUCK_PHY_RX_Byte2_40 "依据CAN下载协议";
CM_ SG_ 2149023592 P2D_BUCK_PHY_RX_Byte3_40 "依据CAN下载协议";
CM_ SG_ 2149023592 P2D_BUCK_PHY_RX_Byte4_40 "依据CAN下载协议";
CM_ SG_ 2149023592 P2D_BUCK_PHY_RX_Byte5_40 "依据CAN下载协议";
CM_ SG_ 2149023592 P2D_BUCK_PHY_RX_Byte6_40 "依据CAN下载协议";
CM_ SG_ 2149023592 P2D_BUCK_PHY_RX_Byte7_40 "依据CAN下载协议";
CM_ SG_ 2149023592 P2D_BUCK_PHY_RX_Byte8_40 "依据CAN下载协议";
CM_ SG_ 2149023593 P2D_BUCK_PHY_RX_Byte1_41 "依据CAN下载协议";
CM_ SG_ 2149023593 P2D_BUCK_PHY_RX_Byte2_41 "依据CAN下载协议";
CM_ SG_ 2149023593 P2D_BUCK_PHY_RX_Byte3_41 "依据CAN下载协议";
CM_ SG_ 2149023593 P2D_BUCK_PHY_RX_Byte4_41 "依据CAN下载协议";
CM_ SG_ 2149023593 P2D_BUCK_PHY_RX_Byte5_41 "依据CAN下载协议";
CM_ SG_ 2149023593 P2D_BUCK_PHY_RX_Byte6_41 "依据CAN下载协议";
CM_ SG_ 2149023593 P2D_BUCK_PHY_RX_Byte7_41 "依据CAN下载协议";
CM_ SG_ 2149023593 P2D_BUCK_PHY_RX_Byte8_41 "依据CAN下载协议";
CM_ SG_ 2149023594 P2D_BUCK_PHY_RX_Byte1_42 "依据CAN下载协议";
CM_ SG_ 2149023594 P2D_BUCK_PHY_RX_Byte2_42 "依据CAN下载协议";
CM_ SG_ 2149023594 P2D_BUCK_PHY_RX_Byte3_42 "依据CAN下载协议";
CM_ SG_ 2149023594 P2D_BUCK_PHY_RX_Byte4_42 "依据CAN下载协议";
CM_ SG_ 2149023594 P2D_BUCK_PHY_RX_Byte5_42 "依据CAN下载协议";
CM_ SG_ 2149023594 P2D_BUCK_PHY_RX_Byte6_42 "依据CAN下载协议";
CM_ SG_ 2149023594 P2D_BUCK_PHY_RX_Byte7_42 "依据CAN下载协议";
CM_ SG_ 2149023594 P2D_BUCK_PHY_RX_Byte8_42 "依据CAN下载协议";
CM_ SG_ 2149023595 P2D_BUCK_PHY_RX_Byte1_43 "依据CAN下载协议";
CM_ SG_ 2149023595 P2D_BUCK_PHY_RX_Byte2_43 "依据CAN下载协议";
CM_ SG_ 2149023595 P2D_BUCK_PHY_RX_Byte3_43 "依据CAN下载协议";
CM_ SG_ 2149023595 P2D_BUCK_PHY_RX_Byte4_43 "依据CAN下载协议";
CM_ SG_ 2149023595 P2D_BUCK_PHY_RX_Byte5_43 "依据CAN下载协议";
CM_ SG_ 2149023595 P2D_BUCK_PHY_RX_Byte6_43 "依据CAN下载协议";
CM_ SG_ 2149023595 P2D_BUCK_PHY_RX_Byte7_43 "依据CAN下载协议";
CM_ SG_ 2149023595 P2D_BUCK_PHY_RX_Byte8_43 "依据CAN下载协议";
CM_ SG_ 2149023596 P2D_BUCK_PHY_RX_Byte1_44 "依据CAN下载协议";
CM_ SG_ 2149023596 P2D_BUCK_PHY_RX_Byte2_44 "依据CAN下载协议";
CM_ SG_ 2149023596 P2D_BUCK_PHY_RX_Byte3_44 "依据CAN下载协议";
CM_ SG_ 2149023596 P2D_BUCK_PHY_RX_Byte4_44 "依据CAN下载协议";
CM_ SG_ 2149023596 P2D_BUCK_PHY_RX_Byte5_44 "依据CAN下载协议";
CM_ SG_ 2149023596 P2D_BUCK_PHY_RX_Byte6_44 "依据CAN下载协议";
CM_ SG_ 2149023596 P2D_BUCK_PHY_RX_Byte7_44 "依据CAN下载协议";
CM_ SG_ 2149023596 P2D_BUCK_PHY_RX_Byte8_44 "依据CAN下载协议";
CM_ SG_ 2149023597 P2D_BUCK_PHY_RX_Byte1_45 "依据CAN下载协议";
CM_ SG_ 2149023597 P2D_BUCK_PHY_RX_Byte2_45 "依据CAN下载协议";
CM_ SG_ 2149023597 P2D_BUCK_PHY_RX_Byte3_45 "依据CAN下载协议";
CM_ SG_ 2149023597 P2D_BUCK_PHY_RX_Byte4_45 "依据CAN下载协议";
CM_ SG_ 2149023597 P2D_BUCK_PHY_RX_Byte5_45 "依据CAN下载协议";
CM_ SG_ 2149023597 P2D_BUCK_PHY_RX_Byte6_45 "依据CAN下载协议";
CM_ SG_ 2149023597 P2D_BUCK_PHY_RX_Byte7_45 "依据CAN下载协议";
CM_ SG_ 2149023597 P2D_BUCK_PHY_RX_Byte8_45 "依据CAN下载协议";
CM_ SG_ 2149023598 P2D_BUCK_PHY_RX_Byte1_46 "依据CAN下载协议";
CM_ SG_ 2149023598 P2D_BUCK_PHY_RX_Byte2_46 "依据CAN下载协议";
CM_ SG_ 2149023598 P2D_BUCK_PHY_RX_Byte3_46 "依据CAN下载协议";
CM_ SG_ 2149023598 P2D_BUCK_PHY_RX_Byte4_46 "依据CAN下载协议";
CM_ SG_ 2149023598 P2D_BUCK_PHY_RX_Byte5_46 "依据CAN下载协议";
CM_ SG_ 2149023598 P2D_BUCK_PHY_RX_Byte6_46 "依据CAN下载协议";
CM_ SG_ 2149023598 P2D_BUCK_PHY_RX_Byte7_46 "依据CAN下载协议";
CM_ SG_ 2149023598 P2D_BUCK_PHY_RX_Byte8_46 "依据CAN下载协议";
CM_ SG_ 2149023599 P2D_BUCK_PHY_RX_Byte1_47 "依据CAN下载协议";
CM_ SG_ 2149023599 P2D_BUCK_PHY_RX_Byte2_47 "依据CAN下载协议";
CM_ SG_ 2149023599 P2D_BUCK_PHY_RX_Byte3_47 "依据CAN下载协议";
CM_ SG_ 2149023599 P2D_BUCK_PHY_RX_Byte4_47 "依据CAN下载协议";
CM_ SG_ 2149023599 P2D_BUCK_PHY_RX_Byte5_47 "依据CAN下载协议";
CM_ SG_ 2149023599 P2D_BUCK_PHY_RX_Byte6_47 "依据CAN下载协议";
CM_ SG_ 2149023599 P2D_BUCK_PHY_RX_Byte7_47 "依据CAN下载协议";
CM_ SG_ 2149023599 P2D_BUCK_PHY_RX_Byte8_47 "依据CAN下载协议";
CM_ SG_ 2149023600 P2D_BUCK_PHY_RX_Byte1_48 "依据CAN下载协议";
CM_ SG_ 2149023600 P2D_BUCK_PHY_RX_Byte2_48 "依据CAN下载协议";
CM_ SG_ 2149023600 P2D_BUCK_PHY_RX_Byte3_48 "依据CAN下载协议";
CM_ SG_ 2149023600 P2D_BUCK_PHY_RX_Byte4_48 "依据CAN下载协议";
CM_ SG_ 2149023600 P2D_BUCK_PHY_RX_Byte5_48 "依据CAN下载协议";
CM_ SG_ 2149023600 P2D_BUCK_PHY_RX_Byte6_48 "依据CAN下载协议";
CM_ SG_ 2149023600 P2D_BUCK_PHY_RX_Byte7_48 "依据CAN下载协议";
CM_ SG_ 2149023600 P2D_BUCK_PHY_RX_Byte8_48 "依据CAN下载协议";
CM_ SG_ 2149023601 P2D_BUCK_PHY_RX_Byte1_49 "依据CAN下载协议";
CM_ SG_ 2149023601 P2D_BUCK_PHY_RX_Byte2_49 "依据CAN下载协议";
CM_ SG_ 2149023601 P2D_BUCK_PHY_RX_Byte3_49 "依据CAN下载协议";
CM_ SG_ 2149023601 P2D_BUCK_PHY_RX_Byte4_49 "依据CAN下载协议";
CM_ SG_ 2149023601 P2D_BUCK_PHY_RX_Byte5_49 "依据CAN下载协议";
CM_ SG_ 2149023601 P2D_BUCK_PHY_RX_Byte6_49 "依据CAN下载协议";
CM_ SG_ 2149023601 P2D_BUCK_PHY_RX_Byte7_49 "依据CAN下载协议";
CM_ SG_ 2149023601 P2D_BUCK_PHY_RX_Byte8_49 "依据CAN下载协议";
CM_ SG_ 2149023602 P2D_BUCK_PHY_RX_Byte1_50 "依据CAN下载协议";
CM_ SG_ 2149023602 P2D_BUCK_PHY_RX_Byte2_50 "依据CAN下载协议";
CM_ SG_ 2149023602 P2D_BUCK_PHY_RX_Byte3_50 "依据CAN下载协议";
CM_ SG_ 2149023602 P2D_BUCK_PHY_RX_Byte4_50 "依据CAN下载协议";
CM_ SG_ 2149023602 P2D_BUCK_PHY_RX_Byte5_50 "依据CAN下载协议";
CM_ SG_ 2149023602 P2D_BUCK_PHY_RX_Byte6_50 "依据CAN下载协议";
CM_ SG_ 2149023602 P2D_BUCK_PHY_RX_Byte7_50 "依据CAN下载协议";
CM_ SG_ 2149023602 P2D_BUCK_PHY_RX_Byte8_50 "依据CAN下载协议";
CM_ SG_ 2149023603 P2D_BUCK_PHY_RX_Byte1_51 "依据CAN下载协议";
CM_ SG_ 2149023603 P2D_BUCK_PHY_RX_Byte2_51 "依据CAN下载协议";
CM_ SG_ 2149023603 P2D_BUCK_PHY_RX_Byte3_51 "依据CAN下载协议";
CM_ SG_ 2149023603 P2D_BUCK_PHY_RX_Byte4_51 "依据CAN下载协议";
CM_ SG_ 2149023603 P2D_BUCK_PHY_RX_Byte5_51 "依据CAN下载协议";
CM_ SG_ 2149023603 P2D_BUCK_PHY_RX_Byte6_51 "依据CAN下载协议";
CM_ SG_ 2149023603 P2D_BUCK_PHY_RX_Byte7_51 "依据CAN下载协议";
CM_ SG_ 2149023603 P2D_BUCK_PHY_RX_Byte8_51 "依据CAN下载协议";
CM_ SG_ 2149023604 P2D_BUCK_PHY_RX_Byte1_52 "依据CAN下载协议";
CM_ SG_ 2149023604 P2D_BUCK_PHY_RX_Byte2_52 "依据CAN下载协议";
CM_ SG_ 2149023604 P2D_BUCK_PHY_RX_Byte3_52 "依据CAN下载协议";
CM_ SG_ 2149023604 P2D_BUCK_PHY_RX_Byte4_52 "依据CAN下载协议";
CM_ SG_ 2149023604 P2D_BUCK_PHY_RX_Byte5_52 "依据CAN下载协议";
CM_ SG_ 2149023604 P2D_BUCK_PHY_RX_Byte6_52 "依据CAN下载协议";
CM_ SG_ 2149023604 P2D_BUCK_PHY_RX_Byte7_52 "依据CAN下载协议";
CM_ SG_ 2149023604 P2D_BUCK_PHY_RX_Byte8_52 "依据CAN下载协议";
CM_ SG_ 2149023605 P2D_BUCK_PHY_RX_Byte1_53 "依据CAN下载协议";
CM_ SG_ 2149023605 P2D_BUCK_PHY_RX_Byte2_53 "依据CAN下载协议";
CM_ SG_ 2149023605 P2D_BUCK_PHY_RX_Byte3_53 "依据CAN下载协议";
CM_ SG_ 2149023605 P2D_BUCK_PHY_RX_Byte4_53 "依据CAN下载协议";
CM_ SG_ 2149023605 P2D_BUCK_PHY_RX_Byte5_53 "依据CAN下载协议";
CM_ SG_ 2149023605 P2D_BUCK_PHY_RX_Byte6_53 "依据CAN下载协议";
CM_ SG_ 2149023605 P2D_BUCK_PHY_RX_Byte7_53 "依据CAN下载协议";
CM_ SG_ 2149023605 P2D_BUCK_PHY_RX_Byte8_53 "依据CAN下载协议";
CM_ SG_ 2149023606 P2D_BUCK_PHY_RX_Byte1_54 "依据CAN下载协议";
CM_ SG_ 2149023606 P2D_BUCK_PHY_RX_Byte2_54 "依据CAN下载协议";
CM_ SG_ 2149023606 P2D_BUCK_PHY_RX_Byte3_54 "依据CAN下载协议";
CM_ SG_ 2149023606 P2D_BUCK_PHY_RX_Byte4_54 "依据CAN下载协议";
CM_ SG_ 2149023606 P2D_BUCK_PHY_RX_Byte5_54 "依据CAN下载协议";
CM_ SG_ 2149023606 P2D_BUCK_PHY_RX_Byte6_54 "依据CAN下载协议";
CM_ SG_ 2149023606 P2D_BUCK_PHY_RX_Byte7_54 "依据CAN下载协议";
CM_ SG_ 2149023606 P2D_BUCK_PHY_RX_Byte8_54 "依据CAN下载协议";
CM_ SG_ 2149023607 P2D_BUCK_PHY_RX_Byte1_55 "依据CAN下载协议";
CM_ SG_ 2149023607 P2D_BUCK_PHY_RX_Byte2_55 "依据CAN下载协议";
CM_ SG_ 2149023607 P2D_BUCK_PHY_RX_Byte3_55 "依据CAN下载协议";
CM_ SG_ 2149023607 P2D_BUCK_PHY_RX_Byte4_55 "依据CAN下载协议";
CM_ SG_ 2149023607 P2D_BUCK_PHY_RX_Byte5_55 "依据CAN下载协议";
CM_ SG_ 2149023607 P2D_BUCK_PHY_RX_Byte6_55 "依据CAN下载协议";
CM_ SG_ 2149023607 P2D_BUCK_PHY_RX_Byte7_55 "依据CAN下载协议";
CM_ SG_ 2149023607 P2D_BUCK_PHY_RX_Byte8_55 "依据CAN下载协议";
CM_ SG_ 2149023608 P2D_BUCK_PHY_RX_Byte1_56 "依据CAN下载协议";
CM_ SG_ 2149023608 P2D_BUCK_PHY_RX_Byte2_56 "依据CAN下载协议";
CM_ SG_ 2149023608 P2D_BUCK_PHY_RX_Byte3_56 "依据CAN下载协议";
CM_ SG_ 2149023608 P2D_BUCK_PHY_RX_Byte4_56 "依据CAN下载协议";
CM_ SG_ 2149023608 P2D_BUCK_PHY_RX_Byte5_56 "依据CAN下载协议";
CM_ SG_ 2149023608 P2D_BUCK_PHY_RX_Byte6_56 "依据CAN下载协议";
CM_ SG_ 2149023608 P2D_BUCK_PHY_RX_Byte7_56 "依据CAN下载协议";
CM_ SG_ 2149023608 P2D_BUCK_PHY_RX_Byte8_56 "依据CAN下载协议";
CM_ SG_ 2149023609 P2D_BUCK_PHY_RX_Byte1_57 "依据CAN下载协议";
CM_ SG_ 2149023609 P2D_BUCK_PHY_RX_Byte2_57 "依据CAN下载协议";
CM_ SG_ 2149023609 P2D_BUCK_PHY_RX_Byte3_57 "依据CAN下载协议";
CM_ SG_ 2149023609 P2D_BUCK_PHY_RX_Byte4_57 "依据CAN下载协议";
CM_ SG_ 2149023609 P2D_BUCK_PHY_RX_Byte5_57 "依据CAN下载协议";
CM_ SG_ 2149023609 P2D_BUCK_PHY_RX_Byte6_57 "依据CAN下载协议";
CM_ SG_ 2149023609 P2D_BUCK_PHY_RX_Byte7_57 "依据CAN下载协议";
CM_ SG_ 2149023609 P2D_BUCK_PHY_RX_Byte8_57 "依据CAN下载协议";
CM_ SG_ 2149023610 P2D_BUCK_PHY_RX_Byte1_58 "依据CAN下载协议";
CM_ SG_ 2149023610 P2D_BUCK_PHY_RX_Byte2_58 "依据CAN下载协议";
CM_ SG_ 2149023610 P2D_BUCK_PHY_RX_Byte3_58 "依据CAN下载协议";
CM_ SG_ 2149023610 P2D_BUCK_PHY_RX_Byte4_58 "依据CAN下载协议";
CM_ SG_ 2149023610 P2D_BUCK_PHY_RX_Byte5_58 "依据CAN下载协议";
CM_ SG_ 2149023610 P2D_BUCK_PHY_RX_Byte6_58 "依据CAN下载协议";
CM_ SG_ 2149023610 P2D_BUCK_PHY_RX_Byte7_58 "依据CAN下载协议";
CM_ SG_ 2149023610 P2D_BUCK_PHY_RX_Byte8_58 "依据CAN下载协议";
CM_ SG_ 2149023611 P2D_BUCK_PHY_RX_Byte1_59 "依据CAN下载协议";
CM_ SG_ 2149023611 P2D_BUCK_PHY_RX_Byte2_59 "依据CAN下载协议";
CM_ SG_ 2149023611 P2D_BUCK_PHY_RX_Byte3_59 "依据CAN下载协议";
CM_ SG_ 2149023611 P2D_BUCK_PHY_RX_Byte4_59 "依据CAN下载协议";
CM_ SG_ 2149023611 P2D_BUCK_PHY_RX_Byte5_59 "依据CAN下载协议";
CM_ SG_ 2149023611 P2D_BUCK_PHY_RX_Byte6_59 "依据CAN下载协议";
CM_ SG_ 2149023611 P2D_BUCK_PHY_RX_Byte7_59 "依据CAN下载协议";
CM_ SG_ 2149023611 P2D_BUCK_PHY_RX_Byte8_59 "依据CAN下载协议";
CM_ SG_ 2149023612 P2D_BUCK_PHY_RX_Byte1_60 "依据CAN下载协议";
CM_ SG_ 2149023612 P2D_BUCK_PHY_RX_Byte2_60 "依据CAN下载协议";
CM_ SG_ 2149023612 P2D_BUCK_PHY_RX_Byte3_60 "依据CAN下载协议";
CM_ SG_ 2149023612 P2D_BUCK_PHY_RX_Byte4_60 "依据CAN下载协议";
CM_ SG_ 2149023612 P2D_BUCK_PHY_RX_Byte5_60 "依据CAN下载协议";
CM_ SG_ 2149023612 P2D_BUCK_PHY_RX_Byte6_60 "依据CAN下载协议";
CM_ SG_ 2149023612 P2D_BUCK_PHY_RX_Byte7_60 "依据CAN下载协议";
CM_ SG_ 2149023612 P2D_BUCK_PHY_RX_Byte8_60 "依据CAN下载协议";
CM_ SG_ 2149023613 P2D_BUCK_PHY_RX_Byte1_61 "依据CAN下载协议";
CM_ SG_ 2149023613 P2D_BUCK_PHY_RX_Byte2_61 "依据CAN下载协议";
CM_ SG_ 2149023613 P2D_BUCK_PHY_RX_Byte3_61 "依据CAN下载协议";
CM_ SG_ 2149023613 P2D_BUCK_PHY_RX_Byte4_61 "依据CAN下载协议";
CM_ SG_ 2149023613 P2D_BUCK_PHY_RX_Byte5_61 "依据CAN下载协议";
CM_ SG_ 2149023613 P2D_BUCK_PHY_RX_Byte6_61 "依据CAN下载协议";
CM_ SG_ 2149023613 P2D_BUCK_PHY_RX_Byte7_61 "依据CAN下载协议";
CM_ SG_ 2149023613 P2D_BUCK_PHY_RX_Byte8_61 "依据CAN下载协议";
CM_ SG_ 2149023614 P2D_BUCK_PHY_RX_Byte1_62 "依据CAN下载协议";
CM_ SG_ 2149023614 P2D_BUCK_PHY_RX_Byte2_62 "依据CAN下载协议";
CM_ SG_ 2149023614 P2D_BUCK_PHY_RX_Byte3_62 "依据CAN下载协议";
CM_ SG_ 2149023614 P2D_BUCK_PHY_RX_Byte4_62 "依据CAN下载协议";
CM_ SG_ 2149023614 P2D_BUCK_PHY_RX_Byte5_62 "依据CAN下载协议";
CM_ SG_ 2149023614 P2D_BUCK_PHY_RX_Byte6_62 "依据CAN下载协议";
CM_ SG_ 2149023614 P2D_BUCK_PHY_RX_Byte7_62 "依据CAN下载协议";
CM_ SG_ 2149023614 P2D_BUCK_PHY_RX_Byte8_62 "依据CAN下载协议";
CM_ SG_ 2149023615 P2D_BUCK_PHY_RX_Byte1_63 "依据CAN下载协议";
CM_ SG_ 2149023615 P2D_BUCK_PHY_RX_Byte2_63 "依据CAN下载协议";
CM_ SG_ 2149023615 P2D_BUCK_PHY_RX_Byte3_63 "依据CAN下载协议";
CM_ SG_ 2149023615 P2D_BUCK_PHY_RX_Byte4_63 "依据CAN下载协议";
CM_ SG_ 2149023615 P2D_BUCK_PHY_RX_Byte5_63 "依据CAN下载协议";
CM_ SG_ 2149023615 P2D_BUCK_PHY_RX_Byte6_63 "依据CAN下载协议";
CM_ SG_ 2149023615 P2D_BUCK_PHY_RX_Byte7_63 "依据CAN下载协议";
CM_ SG_ 2149023615 P2D_BUCK_PHY_RX_Byte8_63 "依据CAN下载协议";
CM_ SG_ 2149089089 P2D_BUCK_PHY_TX_Byte1_01 "依据CAN下载协议";
CM_ SG_ 2149089089 P2D_BUCK_PHY_TX_Byte2_01 "依据CAN下载协议";
CM_ SG_ 2149089089 P2D_BUCK_PHY_TX_Byte3_01 "依据CAN下载协议";
CM_ SG_ 2149089089 P2D_BUCK_PHY_TX_Byte4_01 "依据CAN下载协议";
CM_ SG_ 2149089089 P2D_BUCK_PHY_TX_Byte5_01 "依据CAN下载协议";
CM_ SG_ 2149089089 P2D_BUCK_PHY_TX_Byte6_01 "依据CAN下载协议";
CM_ SG_ 2149089089 P2D_BUCK_PHY_TX_Byte7_01 "依据CAN下载协议";
CM_ SG_ 2149089089 P2D_BUCK_PHY_TX_Byte8_01 "依据CAN下载协议";
CM_ SG_ 2149089090 P2D_BUCK_PHY_TX_Byte1_02 "依据CAN下载协议";
CM_ SG_ 2149089090 P2D_BUCK_PHY_TX_Byte2_02 "依据CAN下载协议";
CM_ SG_ 2149089090 P2D_BUCK_PHY_TX_Byte3_02 "依据CAN下载协议";
CM_ SG_ 2149089090 P2D_BUCK_PHY_TX_Byte4_02 "依据CAN下载协议";
CM_ SG_ 2149089090 P2D_BUCK_PHY_TX_Byte5_02 "依据CAN下载协议";
CM_ SG_ 2149089090 P2D_BUCK_PHY_TX_Byte6_02 "依据CAN下载协议";
CM_ SG_ 2149089090 P2D_BUCK_PHY_TX_Byte7_02 "依据CAN下载协议";
CM_ SG_ 2149089090 P2D_BUCK_PHY_TX_Byte8_02 "依据CAN下载协议";
CM_ SG_ 2149089091 P2D_BUCK_PHY_TX_Byte1_03 "依据CAN下载协议";
CM_ SG_ 2149089091 P2D_BUCK_PHY_TX_Byte2_03 "依据CAN下载协议";
CM_ SG_ 2149089091 P2D_BUCK_PHY_TX_Byte3_03 "依据CAN下载协议";
CM_ SG_ 2149089091 P2D_BUCK_PHY_TX_Byte4_03 "依据CAN下载协议";
CM_ SG_ 2149089091 P2D_BUCK_PHY_TX_Byte5_03 "依据CAN下载协议";
CM_ SG_ 2149089091 P2D_BUCK_PHY_TX_Byte6_03 "依据CAN下载协议";
CM_ SG_ 2149089091 P2D_BUCK_PHY_TX_Byte7_03 "依据CAN下载协议";
CM_ SG_ 2149089091 P2D_BUCK_PHY_TX_Byte8_03 "依据CAN下载协议";
CM_ SG_ 2149089092 P2D_BUCK_PHY_TX_Byte1_04 "依据CAN下载协议";
CM_ SG_ 2149089092 P2D_BUCK_PHY_TX_Byte2_04 "依据CAN下载协议";
CM_ SG_ 2149089092 P2D_BUCK_PHY_TX_Byte3_04 "依据CAN下载协议";
CM_ SG_ 2149089092 P2D_BUCK_PHY_TX_Byte4_04 "依据CAN下载协议";
CM_ SG_ 2149089092 P2D_BUCK_PHY_TX_Byte5_04 "依据CAN下载协议";
CM_ SG_ 2149089092 P2D_BUCK_PHY_TX_Byte6_04 "依据CAN下载协议";
CM_ SG_ 2149089092 P2D_BUCK_PHY_TX_Byte7_04 "依据CAN下载协议";
CM_ SG_ 2149089092 P2D_BUCK_PHY_TX_Byte8_04 "依据CAN下载协议";
CM_ SG_ 2149089093 P2D_BUCK_PHY_TX_Byte1_05 "依据CAN下载协议";
CM_ SG_ 2149089093 P2D_BUCK_PHY_TX_Byte2_05 "依据CAN下载协议";
CM_ SG_ 2149089093 P2D_BUCK_PHY_TX_Byte3_05 "依据CAN下载协议";
CM_ SG_ 2149089093 P2D_BUCK_PHY_TX_Byte4_05 "依据CAN下载协议";
CM_ SG_ 2149089093 P2D_BUCK_PHY_TX_Byte5_05 "依据CAN下载协议";
CM_ SG_ 2149089093 P2D_BUCK_PHY_TX_Byte6_05 "依据CAN下载协议";
CM_ SG_ 2149089093 P2D_BUCK_PHY_TX_Byte7_05 "依据CAN下载协议";
CM_ SG_ 2149089093 P2D_BUCK_PHY_TX_Byte8_05 "依据CAN下载协议";
CM_ SG_ 2149089094 P2D_BUCK_PHY_TX_Byte1_06 "依据CAN下载协议";
CM_ SG_ 2149089094 P2D_BUCK_PHY_TX_Byte2_06 "依据CAN下载协议";
CM_ SG_ 2149089094 P2D_BUCK_PHY_TX_Byte3_06 "依据CAN下载协议";
CM_ SG_ 2149089094 P2D_BUCK_PHY_TX_Byte4_06 "依据CAN下载协议";
CM_ SG_ 2149089094 P2D_BUCK_PHY_TX_Byte5_06 "依据CAN下载协议";
CM_ SG_ 2149089094 P2D_BUCK_PHY_TX_Byte6_06 "依据CAN下载协议";
CM_ SG_ 2149089094 P2D_BUCK_PHY_TX_Byte7_06 "依据CAN下载协议";
CM_ SG_ 2149089094 P2D_BUCK_PHY_TX_Byte8_06 "依据CAN下载协议";
CM_ SG_ 2149089095 P2D_BUCK_PHY_TX_Byte1_07 "依据CAN下载协议";
CM_ SG_ 2149089095 P2D_BUCK_PHY_TX_Byte2_07 "依据CAN下载协议";
CM_ SG_ 2149089095 P2D_BUCK_PHY_TX_Byte3_07 "依据CAN下载协议";
CM_ SG_ 2149089095 P2D_BUCK_PHY_TX_Byte4_07 "依据CAN下载协议";
CM_ SG_ 2149089095 P2D_BUCK_PHY_TX_Byte5_07 "依据CAN下载协议";
CM_ SG_ 2149089095 P2D_BUCK_PHY_TX_Byte6_07 "依据CAN下载协议";
CM_ SG_ 2149089095 P2D_BUCK_PHY_TX_Byte7_07 "依据CAN下载协议";
CM_ SG_ 2149089095 P2D_BUCK_PHY_TX_Byte8_07 "依据CAN下载协议";
CM_ SG_ 2149089096 P2D_BUCK_PHY_TX_Byte1_08 "依据CAN下载协议";
CM_ SG_ 2149089096 P2D_BUCK_PHY_TX_Byte2_08 "依据CAN下载协议";
CM_ SG_ 2149089096 P2D_BUCK_PHY_TX_Byte3_08 "依据CAN下载协议";
CM_ SG_ 2149089096 P2D_BUCK_PHY_TX_Byte4_08 "依据CAN下载协议";
CM_ SG_ 2149089096 P2D_BUCK_PHY_TX_Byte5_08 "依据CAN下载协议";
CM_ SG_ 2149089096 P2D_BUCK_PHY_TX_Byte6_08 "依据CAN下载协议";
CM_ SG_ 2149089096 P2D_BUCK_PHY_TX_Byte7_08 "依据CAN下载协议";
CM_ SG_ 2149089096 P2D_BUCK_PHY_TX_Byte8_08 "依据CAN下载协议";
CM_ SG_ 2149089097 P2D_BUCK_PHY_TX_Byte1_09 "依据CAN下载协议";
CM_ SG_ 2149089097 P2D_BUCK_PHY_TX_Byte2_09 "依据CAN下载协议";
CM_ SG_ 2149089097 P2D_BUCK_PHY_TX_Byte3_09 "依据CAN下载协议";
CM_ SG_ 2149089097 P2D_BUCK_PHY_TX_Byte4_09 "依据CAN下载协议";
CM_ SG_ 2149089097 P2D_BUCK_PHY_TX_Byte5_09 "依据CAN下载协议";
CM_ SG_ 2149089097 P2D_BUCK_PHY_TX_Byte6_09 "依据CAN下载协议";
CM_ SG_ 2149089097 P2D_BUCK_PHY_TX_Byte7_09 "依据CAN下载协议";
CM_ SG_ 2149089097 P2D_BUCK_PHY_TX_Byte8_09 "依据CAN下载协议";
CM_ SG_ 2149089098 P2D_BUCK_PHY_TX_Byte1_10 "依据CAN下载协议";
CM_ SG_ 2149089098 P2D_BUCK_PHY_TX_Byte2_10 "依据CAN下载协议";
CM_ SG_ 2149089098 P2D_BUCK_PHY_TX_Byte3_10 "依据CAN下载协议";
CM_ SG_ 2149089098 P2D_BUCK_PHY_TX_Byte4_10 "依据CAN下载协议";
CM_ SG_ 2149089098 P2D_BUCK_PHY_TX_Byte5_10 "依据CAN下载协议";
CM_ SG_ 2149089098 P2D_BUCK_PHY_TX_Byte6_10 "依据CAN下载协议";
CM_ SG_ 2149089098 P2D_BUCK_PHY_TX_Byte7_10 "依据CAN下载协议";
CM_ SG_ 2149089098 P2D_BUCK_PHY_TX_Byte8_10 "依据CAN下载协议";
CM_ SG_ 2149089099 P2D_BUCK_PHY_TX_Byte1_11 "依据CAN下载协议";
CM_ SG_ 2149089099 P2D_BUCK_PHY_TX_Byte2_11 "依据CAN下载协议";
CM_ SG_ 2149089099 P2D_BUCK_PHY_TX_Byte3_11 "依据CAN下载协议";
CM_ SG_ 2149089099 P2D_BUCK_PHY_TX_Byte4_11 "依据CAN下载协议";
CM_ SG_ 2149089099 P2D_BUCK_PHY_TX_Byte5_11 "依据CAN下载协议";
CM_ SG_ 2149089099 P2D_BUCK_PHY_TX_Byte6_11 "依据CAN下载协议";
CM_ SG_ 2149089099 P2D_BUCK_PHY_TX_Byte7_11 "依据CAN下载协议";
CM_ SG_ 2149089099 P2D_BUCK_PHY_TX_Byte8_11 "依据CAN下载协议";
CM_ SG_ 2149089100 P2D_BUCK_PHY_TX_Byte1_12 "依据CAN下载协议";
CM_ SG_ 2149089100 P2D_BUCK_PHY_TX_Byte2_12 "依据CAN下载协议";
CM_ SG_ 2149089100 P2D_BUCK_PHY_TX_Byte3_12 "依据CAN下载协议";
CM_ SG_ 2149089100 P2D_BUCK_PHY_TX_Byte4_12 "依据CAN下载协议";
CM_ SG_ 2149089100 P2D_BUCK_PHY_TX_Byte5_12 "依据CAN下载协议";
CM_ SG_ 2149089100 P2D_BUCK_PHY_TX_Byte6_12 "依据CAN下载协议";
CM_ SG_ 2149089100 P2D_BUCK_PHY_TX_Byte7_12 "依据CAN下载协议";
CM_ SG_ 2149089100 P2D_BUCK_PHY_TX_Byte8_12 "依据CAN下载协议";
CM_ SG_ 2149089101 P2D_BUCK_PHY_TX_Byte1_13 "依据CAN下载协议";
CM_ SG_ 2149089101 P2D_BUCK_PHY_TX_Byte2_13 "依据CAN下载协议";
CM_ SG_ 2149089101 P2D_BUCK_PHY_TX_Byte3_13 "依据CAN下载协议";
CM_ SG_ 2149089101 P2D_BUCK_PHY_TX_Byte4_13 "依据CAN下载协议";
CM_ SG_ 2149089101 P2D_BUCK_PHY_TX_Byte5_13 "依据CAN下载协议";
CM_ SG_ 2149089101 P2D_BUCK_PHY_TX_Byte6_13 "依据CAN下载协议";
CM_ SG_ 2149089101 P2D_BUCK_PHY_TX_Byte7_13 "依据CAN下载协议";
CM_ SG_ 2149089101 P2D_BUCK_PHY_TX_Byte8_13 "依据CAN下载协议";
CM_ SG_ 2149089102 P2D_BUCK_PHY_TX_Byte1_14 "依据CAN下载协议";
CM_ SG_ 2149089102 P2D_BUCK_PHY_TX_Byte2_14 "依据CAN下载协议";
CM_ SG_ 2149089102 P2D_BUCK_PHY_TX_Byte3_14 "依据CAN下载协议";
CM_ SG_ 2149089102 P2D_BUCK_PHY_TX_Byte4_14 "依据CAN下载协议";
CM_ SG_ 2149089102 P2D_BUCK_PHY_TX_Byte5_14 "依据CAN下载协议";
CM_ SG_ 2149089102 P2D_BUCK_PHY_TX_Byte6_14 "依据CAN下载协议";
CM_ SG_ 2149089102 P2D_BUCK_PHY_TX_Byte7_14 "依据CAN下载协议";
CM_ SG_ 2149089102 P2D_BUCK_PHY_TX_Byte8_14 "依据CAN下载协议";
CM_ SG_ 2149089103 P2D_BUCK_PHY_TX_Byte1_15 "依据CAN下载协议";
CM_ SG_ 2149089103 P2D_BUCK_PHY_TX_Byte2_15 "依据CAN下载协议";
CM_ SG_ 2149089103 P2D_BUCK_PHY_TX_Byte3_15 "依据CAN下载协议";
CM_ SG_ 2149089103 P2D_BUCK_PHY_TX_Byte4_15 "依据CAN下载协议";
CM_ SG_ 2149089103 P2D_BUCK_PHY_TX_Byte5_15 "依据CAN下载协议";
CM_ SG_ 2149089103 P2D_BUCK_PHY_TX_Byte6_15 "依据CAN下载协议";
CM_ SG_ 2149089103 P2D_BUCK_PHY_TX_Byte7_15 "依据CAN下载协议";
CM_ SG_ 2149089103 P2D_BUCK_PHY_TX_Byte8_15 "依据CAN下载协议";
CM_ SG_ 2149089104 P2D_BUCK_PHY_TX_Byte1_16 "依据CAN下载协议";
CM_ SG_ 2149089104 P2D_BUCK_PHY_TX_Byte2_16 "依据CAN下载协议";
CM_ SG_ 2149089104 P2D_BUCK_PHY_TX_Byte3_16 "依据CAN下载协议";
CM_ SG_ 2149089104 P2D_BUCK_PHY_TX_Byte4_16 "依据CAN下载协议";
CM_ SG_ 2149089104 P2D_BUCK_PHY_TX_Byte5_16 "依据CAN下载协议";
CM_ SG_ 2149089104 P2D_BUCK_PHY_TX_Byte6_16 "依据CAN下载协议";
CM_ SG_ 2149089104 P2D_BUCK_PHY_TX_Byte7_16 "依据CAN下载协议";
CM_ SG_ 2149089104 P2D_BUCK_PHY_TX_Byte8_16 "依据CAN下载协议";
CM_ SG_ 2149089105 P2D_BUCK_PHY_TX_Byte1_17 "依据CAN下载协议";
CM_ SG_ 2149089105 P2D_BUCK_PHY_TX_Byte2_17 "依据CAN下载协议";
CM_ SG_ 2149089105 P2D_BUCK_PHY_TX_Byte3_17 "依据CAN下载协议";
CM_ SG_ 2149089105 P2D_BUCK_PHY_TX_Byte4_17 "依据CAN下载协议";
CM_ SG_ 2149089105 P2D_BUCK_PHY_TX_Byte5_17 "依据CAN下载协议";
CM_ SG_ 2149089105 P2D_BUCK_PHY_TX_Byte6_17 "依据CAN下载协议";
CM_ SG_ 2149089105 P2D_BUCK_PHY_TX_Byte7_17 "依据CAN下载协议";
CM_ SG_ 2149089105 P2D_BUCK_PHY_TX_Byte8_17 "依据CAN下载协议";
CM_ SG_ 2149089106 P2D_BUCK_PHY_TX_Byte1_18 "依据CAN下载协议";
CM_ SG_ 2149089106 P2D_BUCK_PHY_TX_Byte2_18 "依据CAN下载协议";
CM_ SG_ 2149089106 P2D_BUCK_PHY_TX_Byte3_18 "依据CAN下载协议";
CM_ SG_ 2149089106 P2D_BUCK_PHY_TX_Byte4_18 "依据CAN下载协议";
CM_ SG_ 2149089106 P2D_BUCK_PHY_TX_Byte5_18 "依据CAN下载协议";
CM_ SG_ 2149089106 P2D_BUCK_PHY_TX_Byte6_18 "依据CAN下载协议";
CM_ SG_ 2149089106 P2D_BUCK_PHY_TX_Byte7_18 "依据CAN下载协议";
CM_ SG_ 2149089106 P2D_BUCK_PHY_TX_Byte8_18 "依据CAN下载协议";
CM_ SG_ 2149089107 P2D_BUCK_PHY_TX_Byte1_19 "依据CAN下载协议";
CM_ SG_ 2149089107 P2D_BUCK_PHY_TX_Byte2_19 "依据CAN下载协议";
CM_ SG_ 2149089107 P2D_BUCK_PHY_TX_Byte3_19 "依据CAN下载协议";
CM_ SG_ 2149089107 P2D_BUCK_PHY_TX_Byte4_19 "依据CAN下载协议";
CM_ SG_ 2149089107 P2D_BUCK_PHY_TX_Byte5_19 "依据CAN下载协议";
CM_ SG_ 2149089107 P2D_BUCK_PHY_TX_Byte6_19 "依据CAN下载协议";
CM_ SG_ 2149089107 P2D_BUCK_PHY_TX_Byte7_19 "依据CAN下载协议";
CM_ SG_ 2149089107 P2D_BUCK_PHY_TX_Byte8_19 "依据CAN下载协议";
CM_ SG_ 2149089108 P2D_BUCK_PHY_TX_Byte1_20 "依据CAN下载协议";
CM_ SG_ 2149089108 P2D_BUCK_PHY_TX_Byte2_20 "依据CAN下载协议";
CM_ SG_ 2149089108 P2D_BUCK_PHY_TX_Byte3_20 "依据CAN下载协议";
CM_ SG_ 2149089108 P2D_BUCK_PHY_TX_Byte4_20 "依据CAN下载协议";
CM_ SG_ 2149089108 P2D_BUCK_PHY_TX_Byte5_20 "依据CAN下载协议";
CM_ SG_ 2149089108 P2D_BUCK_PHY_TX_Byte6_20 "依据CAN下载协议";
CM_ SG_ 2149089108 P2D_BUCK_PHY_TX_Byte7_20 "依据CAN下载协议";
CM_ SG_ 2149089108 P2D_BUCK_PHY_TX_Byte8_20 "依据CAN下载协议";
CM_ SG_ 2149089109 P2D_BUCK_PHY_TX_Byte1_21 "依据CAN下载协议";
CM_ SG_ 2149089109 P2D_BUCK_PHY_TX_Byte2_21 "依据CAN下载协议";
CM_ SG_ 2149089109 P2D_BUCK_PHY_TX_Byte3_21 "依据CAN下载协议";
CM_ SG_ 2149089109 P2D_BUCK_PHY_TX_Byte4_21 "依据CAN下载协议";
CM_ SG_ 2149089109 P2D_BUCK_PHY_TX_Byte5_21 "依据CAN下载协议";
CM_ SG_ 2149089109 P2D_BUCK_PHY_TX_Byte6_21 "依据CAN下载协议";
CM_ SG_ 2149089109 P2D_BUCK_PHY_TX_Byte7_21 "依据CAN下载协议";
CM_ SG_ 2149089109 P2D_BUCK_PHY_TX_Byte8_21 "依据CAN下载协议";
CM_ SG_ 2149089110 P2D_BUCK_PHY_TX_Byte1_22 "依据CAN下载协议";
CM_ SG_ 2149089110 P2D_BUCK_PHY_TX_Byte2_22 "依据CAN下载协议";
CM_ SG_ 2149089110 P2D_BUCK_PHY_TX_Byte3_22 "依据CAN下载协议";
CM_ SG_ 2149089110 P2D_BUCK_PHY_TX_Byte4_22 "依据CAN下载协议";
CM_ SG_ 2149089110 P2D_BUCK_PHY_TX_Byte5_22 "依据CAN下载协议";
CM_ SG_ 2149089110 P2D_BUCK_PHY_TX_Byte6_22 "依据CAN下载协议";
CM_ SG_ 2149089110 P2D_BUCK_PHY_TX_Byte7_22 "依据CAN下载协议";
CM_ SG_ 2149089110 P2D_BUCK_PHY_TX_Byte8_22 "依据CAN下载协议";
CM_ SG_ 2149089111 P2D_BUCK_PHY_TX_Byte1_23 "依据CAN下载协议";
CM_ SG_ 2149089111 P2D_BUCK_PHY_TX_Byte2_23 "依据CAN下载协议";
CM_ SG_ 2149089111 P2D_BUCK_PHY_TX_Byte3_23 "依据CAN下载协议";
CM_ SG_ 2149089111 P2D_BUCK_PHY_TX_Byte4_23 "依据CAN下载协议";
CM_ SG_ 2149089111 P2D_BUCK_PHY_TX_Byte5_23 "依据CAN下载协议";
CM_ SG_ 2149089111 P2D_BUCK_PHY_TX_Byte6_23 "依据CAN下载协议";
CM_ SG_ 2149089111 P2D_BUCK_PHY_TX_Byte7_23 "依据CAN下载协议";
CM_ SG_ 2149089111 P2D_BUCK_PHY_TX_Byte8_23 "依据CAN下载协议";
CM_ SG_ 2149089112 P2D_BUCK_PHY_TX_Byte1_24 "依据CAN下载协议";
CM_ SG_ 2149089112 P2D_BUCK_PHY_TX_Byte2_24 "依据CAN下载协议";
CM_ SG_ 2149089112 P2D_BUCK_PHY_TX_Byte3_24 "依据CAN下载协议";
CM_ SG_ 2149089112 P2D_BUCK_PHY_TX_Byte4_24 "依据CAN下载协议";
CM_ SG_ 2149089112 P2D_BUCK_PHY_TX_Byte5_24 "依据CAN下载协议";
CM_ SG_ 2149089112 P2D_BUCK_PHY_TX_Byte6_24 "依据CAN下载协议";
CM_ SG_ 2149089112 P2D_BUCK_PHY_TX_Byte7_24 "依据CAN下载协议";
CM_ SG_ 2149089112 P2D_BUCK_PHY_TX_Byte8_24 "依据CAN下载协议";
CM_ SG_ 2149089113 P2D_BUCK_PHY_TX_Byte1_25 "依据CAN下载协议";
CM_ SG_ 2149089113 P2D_BUCK_PHY_TX_Byte2_25 "依据CAN下载协议";
CM_ SG_ 2149089113 P2D_BUCK_PHY_TX_Byte3_25 "依据CAN下载协议";
CM_ SG_ 2149089113 P2D_BUCK_PHY_TX_Byte4_25 "依据CAN下载协议";
CM_ SG_ 2149089113 P2D_BUCK_PHY_TX_Byte5_25 "依据CAN下载协议";
CM_ SG_ 2149089113 P2D_BUCK_PHY_TX_Byte6_25 "依据CAN下载协议";
CM_ SG_ 2149089113 P2D_BUCK_PHY_TX_Byte7_25 "依据CAN下载协议";
CM_ SG_ 2149089113 P2D_BUCK_PHY_TX_Byte8_25 "依据CAN下载协议";
CM_ SG_ 2149089114 P2D_BUCK_PHY_TX_Byte1_26 "依据CAN下载协议";
CM_ SG_ 2149089114 P2D_BUCK_PHY_TX_Byte2_26 "依据CAN下载协议";
CM_ SG_ 2149089114 P2D_BUCK_PHY_TX_Byte3_26 "依据CAN下载协议";
CM_ SG_ 2149089114 P2D_BUCK_PHY_TX_Byte4_26 "依据CAN下载协议";
CM_ SG_ 2149089114 P2D_BUCK_PHY_TX_Byte5_26 "依据CAN下载协议";
CM_ SG_ 2149089114 P2D_BUCK_PHY_TX_Byte6_26 "依据CAN下载协议";
CM_ SG_ 2149089114 P2D_BUCK_PHY_TX_Byte7_26 "依据CAN下载协议";
CM_ SG_ 2149089114 P2D_BUCK_PHY_TX_Byte8_26 "依据CAN下载协议";
CM_ SG_ 2149089115 P2D_BUCK_PHY_TX_Byte1_27 "依据CAN下载协议";
CM_ SG_ 2149089115 P2D_BUCK_PHY_TX_Byte2_27 "依据CAN下载协议";
CM_ SG_ 2149089115 P2D_BUCK_PHY_TX_Byte3_27 "依据CAN下载协议";
CM_ SG_ 2149089115 P2D_BUCK_PHY_TX_Byte4_27 "依据CAN下载协议";
CM_ SG_ 2149089115 P2D_BUCK_PHY_TX_Byte5_27 "依据CAN下载协议";
CM_ SG_ 2149089115 P2D_BUCK_PHY_TX_Byte6_27 "依据CAN下载协议";
CM_ SG_ 2149089115 P2D_BUCK_PHY_TX_Byte7_27 "依据CAN下载协议";
CM_ SG_ 2149089115 P2D_BUCK_PHY_TX_Byte8_27 "依据CAN下载协议";
CM_ SG_ 2149089116 P2D_BUCK_PHY_TX_Byte1_28 "依据CAN下载协议";
CM_ SG_ 2149089116 P2D_BUCK_PHY_TX_Byte2_28 "依据CAN下载协议";
CM_ SG_ 2149089116 P2D_BUCK_PHY_TX_Byte3_28 "依据CAN下载协议";
CM_ SG_ 2149089116 P2D_BUCK_PHY_TX_Byte4_28 "依据CAN下载协议";
CM_ SG_ 2149089116 P2D_BUCK_PHY_TX_Byte5_28 "依据CAN下载协议";
CM_ SG_ 2149089116 P2D_BUCK_PHY_TX_Byte6_28 "依据CAN下载协议";
CM_ SG_ 2149089116 P2D_BUCK_PHY_TX_Byte7_28 "依据CAN下载协议";
CM_ SG_ 2149089116 P2D_BUCK_PHY_TX_Byte8_28 "依据CAN下载协议";
CM_ SG_ 2149089117 P2D_BUCK_PHY_TX_Byte1_29 "依据CAN下载协议";
CM_ SG_ 2149089117 P2D_BUCK_PHY_TX_Byte2_29 "依据CAN下载协议";
CM_ SG_ 2149089117 P2D_BUCK_PHY_TX_Byte3_29 "依据CAN下载协议";
CM_ SG_ 2149089117 P2D_BUCK_PHY_TX_Byte4_29 "依据CAN下载协议";
CM_ SG_ 2149089117 P2D_BUCK_PHY_TX_Byte5_29 "依据CAN下载协议";
CM_ SG_ 2149089117 P2D_BUCK_PHY_TX_Byte6_29 "依据CAN下载协议";
CM_ SG_ 2149089117 P2D_BUCK_PHY_TX_Byte7_29 "依据CAN下载协议";
CM_ SG_ 2149089117 P2D_BUCK_PHY_TX_Byte8_29 "依据CAN下载协议";
CM_ SG_ 2149089118 P2D_BUCK_PHY_TX_Byte1_30 "依据CAN下载协议";
CM_ SG_ 2149089118 P2D_BUCK_PHY_TX_Byte2_30 "依据CAN下载协议";
CM_ SG_ 2149089118 P2D_BUCK_PHY_TX_Byte3_30 "依据CAN下载协议";
CM_ SG_ 2149089118 P2D_BUCK_PHY_TX_Byte4_30 "依据CAN下载协议";
CM_ SG_ 2149089118 P2D_BUCK_PHY_TX_Byte5_30 "依据CAN下载协议";
CM_ SG_ 2149089118 P2D_BUCK_PHY_TX_Byte6_30 "依据CAN下载协议";
CM_ SG_ 2149089118 P2D_BUCK_PHY_TX_Byte7_30 "依据CAN下载协议";
CM_ SG_ 2149089118 P2D_BUCK_PHY_TX_Byte8_30 "依据CAN下载协议";
CM_ SG_ 2149089119 P2D_BUCK_PHY_TX_Byte1_31 "依据CAN下载协议";
CM_ SG_ 2149089119 P2D_BUCK_PHY_TX_Byte2_31 "依据CAN下载协议";
CM_ SG_ 2149089119 P2D_BUCK_PHY_TX_Byte3_31 "依据CAN下载协议";
CM_ SG_ 2149089119 P2D_BUCK_PHY_TX_Byte4_31 "依据CAN下载协议";
CM_ SG_ 2149089119 P2D_BUCK_PHY_TX_Byte5_31 "依据CAN下载协议";
CM_ SG_ 2149089119 P2D_BUCK_PHY_TX_Byte6_31 "依据CAN下载协议";
CM_ SG_ 2149089119 P2D_BUCK_PHY_TX_Byte7_31 "依据CAN下载协议";
CM_ SG_ 2149089119 P2D_BUCK_PHY_TX_Byte8_31 "依据CAN下载协议";
CM_ SG_ 2149089120 P2D_BUCK_PHY_TX_Byte1_32 "依据CAN下载协议";
CM_ SG_ 2149089120 P2D_BUCK_PHY_TX_Byte2_32 "依据CAN下载协议";
CM_ SG_ 2149089120 P2D_BUCK_PHY_TX_Byte3_32 "依据CAN下载协议";
CM_ SG_ 2149089120 P2D_BUCK_PHY_TX_Byte4_32 "依据CAN下载协议";
CM_ SG_ 2149089120 P2D_BUCK_PHY_TX_Byte5_32 "依据CAN下载协议";
CM_ SG_ 2149089120 P2D_BUCK_PHY_TX_Byte6_32 "依据CAN下载协议";
CM_ SG_ 2149089120 P2D_BUCK_PHY_TX_Byte7_32 "依据CAN下载协议";
CM_ SG_ 2149089120 P2D_BUCK_PHY_TX_Byte8_32 "依据CAN下载协议";
VAL_ 2148892521 M2D_IDX_CMD_Type_41 0 "Invalid" 2 "Code Index" 5 "Confirm Index" 6 "Exit Code" 7 "Start Code" 8 "Code Failed" 9 "Code Success" 10 "Invalid" 255 "Null" ;
VAL_ 2148892521 M2D_IDX_DCDC_Index_41 0 "Initial Index" 1 "Index 1" 2 "Index 2" 3 "Index 3" 4 "Index 4" 5 "Index 5" 6 "Index 6" 7 "Index 7" 8 "Index 8" 9 "Index 9" 10 "Index 10" 11 "Index 11" 12 "Index 12" 13 "Index 13" 14 "Index 14" 15 "Index 15" 255 "Null" ;
VAL_ 2148892522 M2D_IDX_CMD_Type_42 0 "Invalid" 2 "Code Index" 5 "Confirm Index" 6 "Exit Code" 7 "Start Code" 8 "Code Failed" 9 "Code Success" 10 "Invalid" 255 "Null" ;
VAL_ 2148892522 M2D_IDX_DCDC_Index_42 0 "Initial Index" 1 "Index 1" 2 "Index 2" 3 "Index 3" 4 "Index 4" 5 "Index 5" 6 "Index 6" 7 "Index 7" 8 "Index 8" 9 "Index 9" 10 "Index 10" 11 "Index 11" 12 "Index 12" 13 "Index 13" 14 "Index 14" 15 "Index 15" 255 "Null" ;
VAL_ 2148892523 M2D_IDX_CMD_Type_43 0 "Invalid" 2 "Code Index" 5 "Confirm Index" 6 "Exit Code" 7 "Start Code" 8 "Code Failed" 9 "Code Success" 10 "Invalid" 255 "Null" ;
VAL_ 2148892523 M2D_IDX_DCDC_Index_43 0 "Initial Index" 1 "Index 1" 2 "Index 2" 3 "Index 3" 4 "Index 4" 5 "Index 5" 6 "Index 6" 7 "Index 7" 8 "Index 8" 9 "Index 9" 10 "Index 10" 11 "Index 11" 12 "Index 12" 13 "Index 13" 14 "Index 14" 15 "Index 15" 255 "Null" ;
VAL_ 2148892524 M2D_IDX_CMD_Type_44 0 "Invalid" 2 "Code Index" 5 "Confirm Index" 6 "Exit Code" 7 "Start Code" 8 "Code Failed" 9 "Code Success" 10 "Invalid" 255 "Null" ;
VAL_ 2148892524 M2D_IDX_DCDC_Index_44 0 "Initial Index" 1 "Index 1" 2 "Index 2" 3 "Index 3" 4 "Index 4" 5 "Index 5" 6 "Index 6" 7 "Index 7" 8 "Index 8" 9 "Index 9" 10 "Index 10" 11 "Index 11" 12 "Index 12" 13 "Index 13" 14 "Index 14" 15 "Index 15" 255 "Null" ;
VAL_ 2148892525 M2D_IDX_CMD_Type_45 0 "Invalid" 2 "Code Index" 5 "Confirm Index" 6 "Exit Code" 7 "Start Code" 8 "Code Failed" 9 "Code Success" 10 "Invalid" 255 "Null" ;
VAL_ 2148892525 M2D_IDX_DCDC_Index_45 0 "Initial Index" 1 "Index 1" 2 "Index 2" 3 "Index 3" 4 "Index 4" 5 "Index 5" 6 "Index 6" 7 "Index 7" 8 "Index 8" 9 "Index 9" 10 "Index 10" 11 "Index 11" 12 "Index 12" 13 "Index 13" 14 "Index 14" 15 "Index 15" 255 "Null" ;
VAL_ 2148892526 M2D_IDX_CMD_Type_46 0 "Invalid" 2 "Code Index" 5 "Confirm Index" 6 "Exit Code" 7 "Start Code" 8 "Code Failed" 9 "Code Success" 10 "Invalid" 255 "Null" ;
VAL_ 2148892526 M2D_IDX_DCDC_Index_46 0 "Initial Index" 1 "Index 1" 2 "Index 2" 3 "Index 3" 4 "Index 4" 5 "Index 5" 6 "Index 6" 7 "Index 7" 8 "Index 8" 9 "Index 9" 10 "Index 10" 11 "Index 11" 12 "Index 12" 13 "Index 13" 14 "Index 14" 15 "Index 15" 255 "Null" ;
VAL_ 2148892527 M2D_IDX_CMD_Type_47 0 "Invalid" 2 "Code Index" 5 "Confirm Index" 6 "Exit Code" 7 "Start Code" 8 "Code Failed" 9 "Code Success" 10 "Invalid" 255 "Null" ;
VAL_ 2148892527 M2D_IDX_DCDC_Index_47 0 "Initial Index" 1 "Index 1" 2 "Index 2" 3 "Index 3" 4 "Index 4" 5 "Index 5" 6 "Index 6" 7 "Index 7" 8 "Index 8" 9 "Index 9" 10 "Index 10" 11 "Index 11" 12 "Index 12" 13 "Index 13" 14 "Index 14" 15 "Index 15" 255 "Null" ;
VAL_ 2148892528 M2D_IDX_CMD_Type_48 0 "Invalid" 2 "Code Index" 5 "Confirm Index" 6 "Exit Code" 7 "Start Code" 8 "Code Failed" 9 "Code Success" 10 "Invalid" 255 "Null" ;
VAL_ 2148892528 M2D_IDX_DCDC_Index_48 0 "Initial Index" 1 "Index 1" 2 "Index 2" 3 "Index 3" 4 "Index 4" 5 "Index 5" 6 "Index 6" 7 "Index 7" 8 "Index 8" 9 "Index 9" 10 "Index 10" 11 "Index 11" 12 "Index 12" 13 "Index 13" 14 "Index 14" 15 "Index 15" 255 "Null" ;
VAL_ 2148892529 M2D_IDX_CMD_Type_49 0 "Invalid" 2 "Code Index" 5 "Confirm Index" 6 "Exit Code" 7 "Start Code" 8 "Code Failed" 9 "Code Success" 10 "Invalid" 255 "Null" ;
VAL_ 2148892529 M2D_IDX_DCDC_Index_49 0 "Initial Index" 1 "Index 1" 2 "Index 2" 3 "Index 3" 4 "Index 4" 5 "Index 5" 6 "Index 6" 7 "Index 7" 8 "Index 8" 9 "Index 9" 10 "Index 10" 11 "Index 11" 12 "Index 12" 13 "Index 13" 14 "Index 14" 15 "Index 15" 255 "Null" ;
VAL_ 2148892530 M2D_IDX_CMD_Type_50 0 "Invalid" 2 "Code Index" 5 "Confirm Index" 6 "Exit Code" 7 "Start Code" 8 "Code Failed" 9 "Code Success" 10 "Invalid" 255 "Null" ;
VAL_ 2148892530 M2D_IDX_DCDC_Index_50 0 "Initial Index" 1 "Index 1" 2 "Index 2" 3 "Index 3" 4 "Index 4" 5 "Index 5" 6 "Index 6" 7 "Index 7" 8 "Index 8" 9 "Index 9" 10 "Index 10" 11 "Index 11" 12 "Index 12" 13 "Index 13" 14 "Index 14" 15 "Index 15" 255 "Null" ;
VAL_ 2148892531 M2D_IDX_CMD_Type_51 0 "Invalid" 2 "Code Index" 5 "Confirm Index" 6 "Exit Code" 7 "Start Code" 8 "Code Failed" 9 "Code Success" 10 "Invalid" 255 "Null" ;
VAL_ 2148892531 M2D_IDX_DCDC_Index_51 0 "Initial Index" 1 "Index 1" 2 "Index 2" 3 "Index 3" 4 "Index 4" 5 "Index 5" 6 "Index 6" 7 "Index 7" 8 "Index 8" 9 "Index 9" 10 "Index 10" 11 "Index 11" 12 "Index 12" 13 "Index 13" 14 "Index 14" 15 "Index 15" 255 "Null" ;
VAL_ 2148892532 M2D_IDX_CMD_Type_52 0 "Invalid" 2 "Code Index" 5 "Confirm Index" 6 "Exit Code" 7 "Start Code" 8 "Code Failed" 9 "Code Success" 10 "Invalid" 255 "Null" ;
VAL_ 2148892532 M2D_IDX_DCDC_Index_52 0 "Initial Index" 1 "Index 1" 2 "Index 2" 3 "Index 3" 4 "Index 4" 5 "Index 5" 6 "Index 6" 7 "Index 7" 8 "Index 8" 9 "Index 9" 10 "Index 10" 11 "Index 11" 12 "Index 12" 13 "Index 13" 14 "Index 14" 15 "Index 15" 255 "Null" ;
VAL_ 2148892533 M2D_IDX_CMD_Type_53 0 "Invalid" 2 "Code Index" 5 "Confirm Index" 6 "Exit Code" 7 "Start Code" 8 "Code Failed" 9 "Code Success" 10 "Invalid" 255 "Null" ;
VAL_ 2148892533 M2D_IDX_DCDC_Index_53 0 "Initial Index" 1 "Index 1" 2 "Index 2" 3 "Index 3" 4 "Index 4" 5 "Index 5" 6 "Index 6" 7 "Index 7" 8 "Index 8" 9 "Index 9" 10 "Index 10" 11 "Index 11" 12 "Index 12" 13 "Index 13" 14 "Index 14" 15 "Index 15" 255 "Null" ;
VAL_ 2148892534 M2D_IDX_CMD_Type_54 0 "Invalid" 2 "Code Index" 5 "Confirm Index" 6 "Exit Code" 7 "Start Code" 8 "Code Failed" 9 "Code Success" 10 "Invalid" 255 "Null" ;
VAL_ 2148892534 M2D_IDX_DCDC_Index_54 0 "Initial Index" 1 "Index 1" 2 "Index 2" 3 "Index 3" 4 "Index 4" 5 "Index 5" 6 "Index 6" 7 "Index 7" 8 "Index 8" 9 "Index 9" 10 "Index 10" 11 "Index 11" 12 "Index 12" 13 "Index 13" 14 "Index 14" 15 "Index 15" 255 "Null" ;
VAL_ 2148892535 M2D_IDX_CMD_Type_55 0 "Invalid" 2 "Code Index" 5 "Confirm Index" 6 "Exit Code" 7 "Start Code" 8 "Code Failed" 9 "Code Success" 10 "Invalid" 255 "Null" ;
VAL_ 2148892535 M2D_IDX_DCDC_Index_55 0 "Initial Index" 1 "Index 1" 2 "Index 2" 3 "Index 3" 4 "Index 4" 5 "Index 5" 6 "Index 6" 7 "Index 7" 8 "Index 8" 9 "Index 9" 10 "Index 10" 11 "Index 11" 12 "Index 12" 13 "Index 13" 14 "Index 14" 15 "Index 15" 255 "Null" ;
VAL_ 2148892536 M2D_IDX_CMD_Type_56 0 "Invalid" 2 "Code Index" 5 "Confirm Index" 6 "Exit Code" 7 "Start Code" 8 "Code Failed" 9 "Code Success" 10 "Invalid" 255 "Null" ;
VAL_ 2148892536 M2D_IDX_DCDC_Index_56 0 "Initial Index" 1 "Index 1" 2 "Index 2" 3 "Index 3" 4 "Index 4" 5 "Index 5" 6 "Index 6" 7 "Index 7" 8 "Index 8" 9 "Index 9" 10 "Index 10" 11 "Index 11" 12 "Index 12" 13 "Index 13" 14 "Index 14" 15 "Index 15" 255 "Null" ;
VAL_ 2148892537 M2D_IDX_CMD_Type_57 0 "Invalid" 2 "Code Index" 5 "Confirm Index" 6 "Exit Code" 7 "Start Code" 8 "Code Failed" 9 "Code Success" 10 "Invalid" 255 "Null" ;
VAL_ 2148892537 M2D_IDX_DCDC_Index_57 0 "Initial Index" 1 "Index 1" 2 "Index 2" 3 "Index 3" 4 "Index 4" 5 "Index 5" 6 "Index 6" 7 "Index 7" 8 "Index 8" 9 "Index 9" 10 "Index 10" 11 "Index 11" 12 "Index 12" 13 "Index 13" 14 "Index 14" 15 "Index 15" 255 "Null" ;
VAL_ 2148892538 M2D_IDX_CMD_Type_58 0 "Invalid" 2 "Code Index" 5 "Confirm Index" 6 "Exit Code" 7 "Start Code" 8 "Code Failed" 9 "Code Success" 10 "Invalid" 255 "Null" ;
VAL_ 2148892538 M2D_IDX_DCDC_Index_58 0 "Initial Index" 1 "Index 1" 2 "Index 2" 3 "Index 3" 4 "Index 4" 5 "Index 5" 6 "Index 6" 7 "Index 7" 8 "Index 8" 9 "Index 9" 10 "Index 10" 11 "Index 11" 12 "Index 12" 13 "Index 13" 14 "Index 14" 15 "Index 15" 255 "Null" ;
VAL_ 2148892539 M2D_IDX_CMD_Type_59 0 "Invalid" 2 "Code Index" 5 "Confirm Index" 6 "Exit Code" 7 "Start Code" 8 "Code Failed" 9 "Code Success" 10 "Invalid" 255 "Null" ;
VAL_ 2148892539 M2D_IDX_DCDC_Index_59 0 "Initial Index" 1 "Index 1" 2 "Index 2" 3 "Index 3" 4 "Index 4" 5 "Index 5" 6 "Index 6" 7 "Index 7" 8 "Index 8" 9 "Index 9" 10 "Index 10" 11 "Index 11" 12 "Index 12" 13 "Index 13" 14 "Index 14" 15 "Index 15" 255 "Null" ;
VAL_ 2148892540 M2D_IDX_CMD_Type_60 0 "Invalid" 2 "Code Index" 5 "Confirm Index" 6 "Exit Code" 7 "Start Code" 8 "Code Failed" 9 "Code Success" 10 "Invalid" 255 "Null" ;
VAL_ 2148892540 M2D_IDX_DCDC_Index_60 0 "Initial Index" 1 "Index 1" 2 "Index 2" 3 "Index 3" 4 "Index 4" 5 "Index 5" 6 "Index 6" 7 "Index 7" 8 "Index 8" 9 "Index 9" 10 "Index 10" 11 "Index 11" 12 "Index 12" 13 "Index 13" 14 "Index 14" 15 "Index 15" 255 "Null" ;
VAL_ 2148892541 M2D_IDX_CMD_Type_61 0 "Invalid" 2 "Code Index" 5 "Confirm Index" 6 "Exit Code" 7 "Start Code" 8 "Code Failed" 9 "Code Success" 10 "Invalid" 255 "Null" ;
VAL_ 2148892541 M2D_IDX_DCDC_Index_61 0 "Initial Index" 1 "Index 1" 2 "Index 2" 3 "Index 3" 4 "Index 4" 5 "Index 5" 6 "Index 6" 7 "Index 7" 8 "Index 8" 9 "Index 9" 10 "Index 10" 11 "Index 11" 12 "Index 12" 13 "Index 13" 14 "Index 14" 15 "Index 15" 255 "Null" ;
VAL_ 2148892542 M2D_IDX_CMD_Type_62 0 "Invalid" 2 "Code Index" 5 "Confirm Index" 6 "Exit Code" 7 "Start Code" 8 "Code Failed" 9 "Code Success" 10 "Invalid" 255 "Null" ;
VAL_ 2148892542 M2D_IDX_DCDC_Index_62 0 "Initial Index" 1 "Index 1" 2 "Index 2" 3 "Index 3" 4 "Index 4" 5 "Index 5" 6 "Index 6" 7 "Index 7" 8 "Index 8" 9 "Index 9" 10 "Index 10" 11 "Index 11" 12 "Index 12" 13 "Index 13" 14 "Index 14" 15 "Index 15" 255 "Null" ;
VAL_ 2148892543 M2D_IDX_CMD_Type_63 0 "Invalid" 2 "Code Index" 5 "Confirm Index" 6 "Exit Code" 7 "Start Code" 8 "Code Failed" 9 "Code Success" 10 "Invalid" 255 "Null" ;
VAL_ 2148892543 M2D_IDX_DCDC_Index_63 0 "Initial Index" 1 "Index 1" 2 "Index 2" 3 "Index 3" 4 "Index 4" 5 "Index 5" 6 "Index 6" 7 "Index 7" 8 "Index 8" 9 "Index 9" 10 "Index 10" 11 "Index 11" 12 "Index 12" 13 "Index 13" 14 "Index 14" 15 "Index 15" 255 "Null" ;
VAL_ 2149034734 P2D_Read_DCDC_Ver_01 0 "ALL DCDC" 1 "DCDC 1" 2 "DCDC 2" 3 "DCDC 3" 4 "DCDC 4" 5 "DCDC 5" 6 "DCDC 6" 7 "DCDC 7" 8 "DCDC 8" 9 "DCDC 9" 10 "DCDC 10" 11 "DCDC 11" 12 "DCDC 12" 13 "DCDC 13" 14 "DCDC 14" 15 "DCDC 15" ;
VAL_ 2149034734 P2D_Read_DCDCSW_Ver_01 0 "Null" 1 "ReadEn" ;
VAL_ 2149034734 P2D_Read_DCDCBoot_Ver_01 0 "Null" 1 "ReadEn" ;
VAL_ 2149034734 P2D_Read_DCDCHW_Ver_01 0 "Null" 1 "ReadEn" ;
VAL_ 2149034734 P2D_Read_DCDC_Barcode_01 0 "Null" 1 "ReadEn" ;
VAL_ 2149034734 P2D_RQ_Read_Detail_Data_01 0 "Null" 1 "ReadEn" ;
VERSION ""

NS_ :

BS_:

BU_: MBMU PC SBMU IMM ETH DCDC LEMS

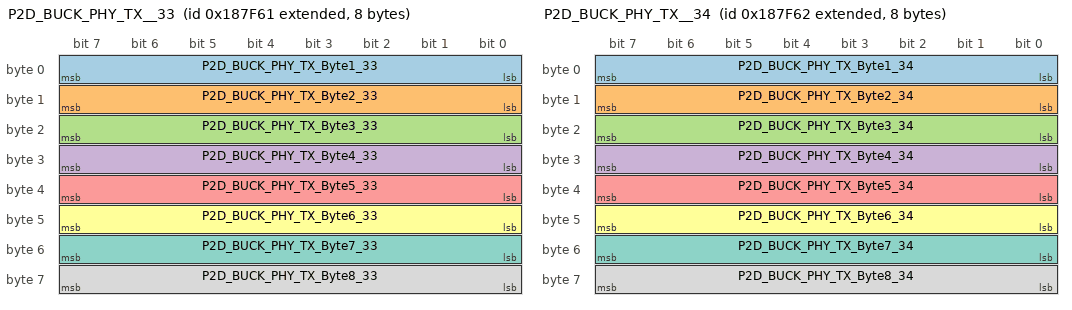
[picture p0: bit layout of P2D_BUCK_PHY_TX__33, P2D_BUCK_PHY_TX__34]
BO_ 2149089121 P2D_BUCK_PHY_TX__33: 8 PC
 SG_ P2D_BUCK_PHY_TX_Byte1_33 : 0|8@1+ (1,0) [0|255] ""  DCDC
 SG_ P2D_BUCK_PHY_TX_Byte2_33 : 8|8@1+ (1,0) [0|255] ""  DCDC
 SG_ P2D_BUCK_PHY_TX_Byte3_33 : 16|8@1+ (1,0) [0|255] ""  DCDC
 SG_ P2D_BUCK_PHY_TX_Byte4_33 : 24|8@1+ (1,0) [0|255] ""  DCDC
 SG_ P2D_BUCK_PHY_TX_Byte5_33 : 32|8@1+ (1,0) [0|255] ""  DCDC
 SG_ P2D_BUCK_PHY_TX_Byte6_33 : 40|8@1+ (1,0) [0|255] ""  DCDC
 SG_ P2D_BUCK_PHY_TX_Byte7_33 : 48|8@1+ (1,0) [0|255] ""  DCDC
 SG_ P2D_BUCK_PHY_TX_Byte8_33 : 56|8@1+ (1,0) [0|255] ""  DCDC

BO_ 2149089122 P2D_BUCK_PHY_TX__34: 8 PC
 SG_ P2D_BUCK_PHY_TX_Byte1_34 : 0|8@1+ (1,0) [0|255] ""  DCDC
 SG_ P2D_BUCK_PHY_TX_Byte2_34 : 8|8@1+ (1,0) [0|255] ""  DCDC
 SG_ P2D_BUCK_PHY_TX_Byte3_34 : 16|8@1+ (1,0) [0|255] ""  DCDC
 SG_ P2D_BUCK_PHY_TX_Byte4_34 : 24|8@1+ (1,0) [0|255] ""  DCDC
 SG_ P2D_BUCK_PHY_TX_Byte5_34 : 32|8@1+ (1,0) [0|255] ""  DCDC
 SG_ P2D_BUCK_PHY_TX_Byte6_34 : 40|8@1+ (1,0) [0|255] ""  DCDC
 SG_ P2D_BUCK_PHY_TX_Byte7_34 : 48|8@1+ (1,0) [0|255] ""  DCDC
 SG_ P2D_BUCK_PHY_TX_Byte8_34 : 56|8@1+ (1,0) [0|255] ""  DCDC

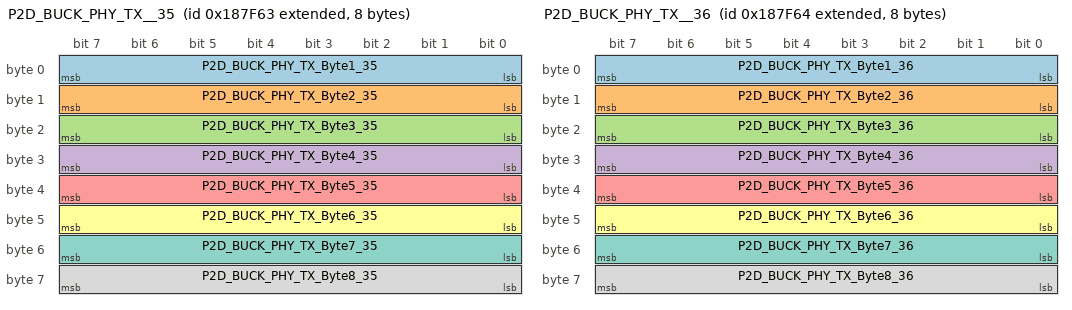
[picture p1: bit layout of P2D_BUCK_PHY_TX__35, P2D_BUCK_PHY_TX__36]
BO_ 2149089123 P2D_BUCK_PHY_TX__35: 8 PC
 SG_ P2D_BUCK_PHY_TX_Byte1_35 : 0|8@1+ (1,0) [0|255] ""  DCDC
 SG_ P2D_BUCK_PHY_TX_Byte2_35 : 8|8@1+ (1,0) [0|255] ""  DCDC
 SG_ P2D_BUCK_PHY_TX_Byte3_35 : 16|8@1+ (1,0) [0|255] ""  DCDC
 SG_ P2D_BUCK_PHY_TX_Byte4_35 : 24|8@1+ (1,0) [0|255] ""  DCDC
 SG_ P2D_BUCK_PHY_TX_Byte5_35 : 32|8@1+ (1,0) [0|255] ""  DCDC
 SG_ P2D_BUCK_PHY_TX_Byte6_35 : 40|8@1+ (1,0) [0|255] ""  DCDC
 SG_ P2D_BUCK_PHY_TX_Byte7_35 : 48|8@1+ (1,0) [0|255] ""  DCDC
 SG_ P2D_BUCK_PHY_TX_Byte8_35 : 56|8@1+ (1,0) [0|255] ""  DCDC

BO_ 2149089124 P2D_BUCK_PHY_TX__36: 8 PC
 SG_ P2D_BUCK_PHY_TX_Byte1_36 : 0|8@1+ (1,0) [0|255] ""  DCDC
 SG_ P2D_BUCK_PHY_TX_Byte2_36 : 8|8@1+ (1,0) [0|255] ""  DCDC
 SG_ P2D_BUCK_PHY_TX_Byte3_36 : 16|8@1+ (1,0) [0|255] ""  DCDC
 SG_ P2D_BUCK_PHY_TX_Byte4_36 : 24|8@1+ (1,0) [0|255] ""  DCDC
 SG_ P2D_BUCK_PHY_TX_Byte5_36 : 32|8@1+ (1,0) [0|255] ""  DCDC
 SG_ P2D_BUCK_PHY_TX_Byte6_36 : 40|8@1+ (1,0) [0|255] ""  DCDC
 SG_ P2D_BUCK_PHY_TX_Byte7_36 : 48|8@1+ (1,0) [0|255] ""  DCDC
 SG_ P2D_BUCK_PHY_TX_Byte8_36 : 56|8@1+ (1,0) [0|255] ""  DCDC

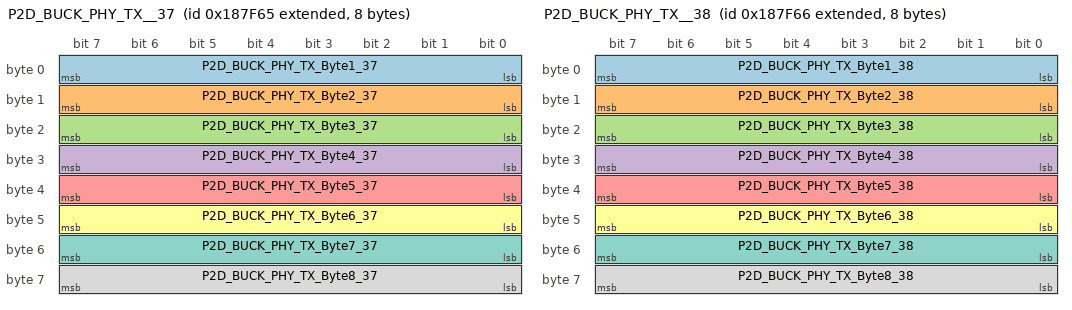
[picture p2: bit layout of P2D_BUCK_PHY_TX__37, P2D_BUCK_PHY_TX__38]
BO_ 2149089125 P2D_BUCK_PHY_TX__37: 8 PC
 SG_ P2D_BUCK_PHY_TX_Byte1_37 : 0|8@1+ (1,0) [0|255] ""  DCDC
 SG_ P2D_BUCK_PHY_TX_Byte2_37 : 8|8@1+ (1,0) [0|255] ""  DCDC
 SG_ P2D_BUCK_PHY_TX_Byte3_37 : 16|8@1+ (1,0) [0|255] ""  DCDC
 SG_ P2D_BUCK_PHY_TX_Byte4_37 : 24|8@1+ (1,0) [0|255] ""  DCDC
 SG_ P2D_BUCK_PHY_TX_Byte5_37 : 32|8@1+ (1,0) [0|255] ""  DCDC
 SG_ P2D_BUCK_PHY_TX_Byte6_37 : 40|8@1+ (1,0) [0|255] ""  DCDC
 SG_ P2D_BUCK_PHY_TX_Byte7_37 : 48|8@1+ (1,0) [0|255] ""  DCDC
 SG_ P2D_BUCK_PHY_TX_Byte8_37 : 56|8@1+ (1,0) [0|255] ""  DCDC

BO_ 2149089126 P2D_BUCK_PHY_TX__38: 8 PC
 SG_ P2D_BUCK_PHY_TX_Byte1_38 : 0|8@1+ (1,0) [0|255] ""  DCDC
 SG_ P2D_BUCK_PHY_TX_Byte2_38 : 8|8@1+ (1,0) [0|255] ""  DCDC
 SG_ P2D_BUCK_PHY_TX_Byte3_38 : 16|8@1+ (1,0) [0|255] ""  DCDC
 SG_ P2D_BUCK_PHY_TX_Byte4_38 : 24|8@1+ (1,0) [0|255] ""  DCDC
 SG_ P2D_BUCK_PHY_TX_Byte5_38 : 32|8@1+ (1,0) [0|255] ""  DCDC
 SG_ P2D_BUCK_PHY_TX_Byte6_38 : 40|8@1+ (1,0) [0|255] ""  DCDC
 SG_ P2D_BUCK_PHY_TX_Byte7_38 : 48|8@1+ (1,0) [0|255] ""  DCDC
 SG_ P2D_BUCK_PHY_TX_Byte8_38 : 56|8@1+ (1,0) [0|255] ""  DCDC

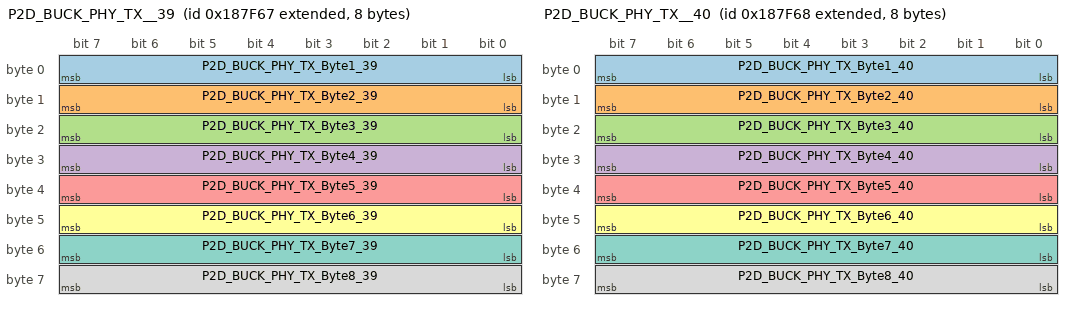
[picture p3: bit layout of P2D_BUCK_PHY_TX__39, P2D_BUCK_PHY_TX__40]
BO_ 2149089127 P2D_BUCK_PHY_TX__39: 8 PC
 SG_ P2D_BUCK_PHY_TX_Byte1_39 : 0|8@1+ (1,0) [0|255] ""  DCDC
 SG_ P2D_BUCK_PHY_TX_Byte2_39 : 8|8@1+ (1,0) [0|255] ""  DCDC
 SG_ P2D_BUCK_PHY_TX_Byte3_39 : 16|8@1+ (1,0) [0|255] ""  DCDC
 SG_ P2D_BUCK_PHY_TX_Byte4_39 : 24|8@1+ (1,0) [0|255] ""  DCDC
 SG_ P2D_BUCK_PHY_TX_Byte5_39 : 32|8@1+ (1,0) [0|255] ""  DCDC
 SG_ P2D_BUCK_PHY_TX_Byte6_39 : 40|8@1+ (1,0) [0|255] ""  DCDC
 SG_ P2D_BUCK_PHY_TX_Byte7_39 : 48|8@1+ (1,0) [0|255] ""  DCDC
 SG_ P2D_BUCK_PHY_TX_Byte8_39 : 56|8@1+ (1,0) [0|255] ""  DCDC

BO_ 2149089128 P2D_BUCK_PHY_TX__40: 8 PC
 SG_ P2D_BUCK_PHY_TX_Byte1_40 : 0|8@1+ (1,0) [0|255] ""  DCDC
 SG_ P2D_BUCK_PHY_TX_Byte2_40 : 8|8@1+ (1,0) [0|255] ""  DCDC
 SG_ P2D_BUCK_PHY_TX_Byte3_40 : 16|8@1+ (1,0) [0|255] ""  DCDC
 SG_ P2D_BUCK_PHY_TX_Byte4_40 : 24|8@1+ (1,0) [0|255] ""  DCDC
 SG_ P2D_BUCK_PHY_TX_Byte5_40 : 32|8@1+ (1,0) [0|255] ""  DCDC
 SG_ P2D_BUCK_PHY_TX_Byte6_40 : 40|8@1+ (1,0) [0|255] ""  DCDC
 SG_ P2D_BUCK_PHY_TX_Byte7_40 : 48|8@1+ (1,0) [0|255] ""  DCDC
 SG_ P2D_BUCK_PHY_TX_Byte8_40 : 56|8@1+ (1,0) [0|255] ""  DCDC

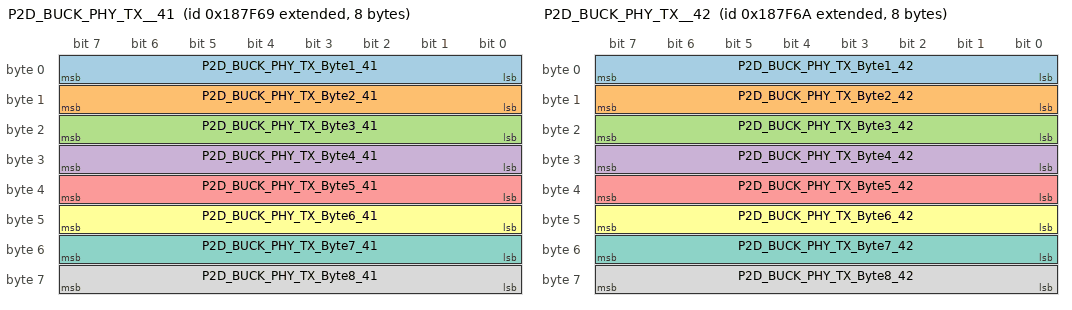
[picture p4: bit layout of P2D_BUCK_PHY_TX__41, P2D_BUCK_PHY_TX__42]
BO_ 2149089129 P2D_BUCK_PHY_TX__41: 8 PC
 SG_ P2D_BUCK_PHY_TX_Byte1_41 : 0|8@1+ (1,0) [0|255] ""  DCDC
 SG_ P2D_BUCK_PHY_TX_Byte2_41 : 8|8@1+ (1,0) [0|255] ""  DCDC
 SG_ P2D_BUCK_PHY_TX_Byte3_41 : 16|8@1+ (1,0) [0|255] ""  DCDC
 SG_ P2D_BUCK_PHY_TX_Byte4_41 : 24|8@1+ (1,0) [0|255] ""  DCDC
 SG_ P2D_BUCK_PHY_TX_Byte5_41 : 32|8@1+ (1,0) [0|255] ""  DCDC
 SG_ P2D_BUCK_PHY_TX_Byte6_41 : 40|8@1+ (1,0) [0|255] ""  DCDC
 SG_ P2D_BUCK_PHY_TX_Byte7_41 : 48|8@1+ (1,0) [0|255] ""  DCDC
 SG_ P2D_BUCK_PHY_TX_Byte8_41 : 56|8@1+ (1,0) [0|255] ""  DCDC

BO_ 2149089130 P2D_BUCK_PHY_TX__42: 8 PC
 SG_ P2D_BUCK_PHY_TX_Byte1_42 : 0|8@1+ (1,0) [0|255] ""  DCDC
 SG_ P2D_BUCK_PHY_TX_Byte2_42 : 8|8@1+ (1,0) [0|255] ""  DCDC
 SG_ P2D_BUCK_PHY_TX_Byte3_42 : 16|8@1+ (1,0) [0|255] ""  DCDC
 SG_ P2D_BUCK_PHY_TX_Byte4_42 : 24|8@1+ (1,0) [0|255] ""  DCDC
 SG_ P2D_BUCK_PHY_TX_Byte5_42 : 32|8@1+ (1,0) [0|255] ""  DCDC
 SG_ P2D_BUCK_PHY_TX_Byte6_42 : 40|8@1+ (1,0) [0|255] ""  DCDC
 SG_ P2D_BUCK_PHY_TX_Byte7_42 : 48|8@1+ (1,0) [0|255] ""  DCDC
 SG_ P2D_BUCK_PHY_TX_Byte8_42 : 56|8@1+ (1,0) [0|255] ""  DCDC

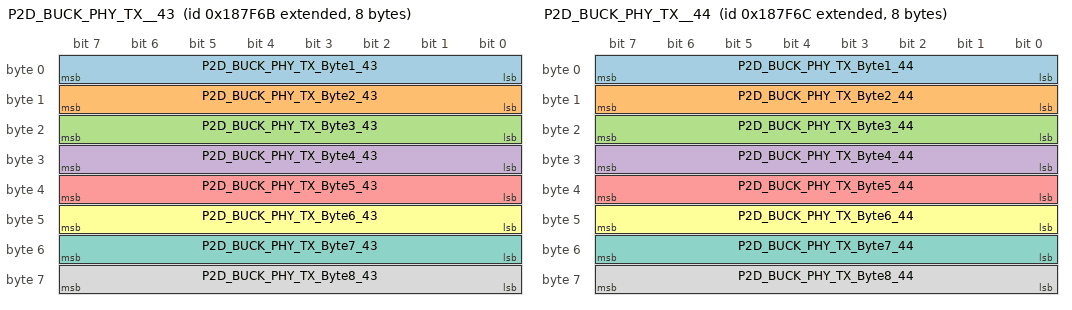
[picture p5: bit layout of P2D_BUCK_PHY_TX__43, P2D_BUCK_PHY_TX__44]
BO_ 2149089131 P2D_BUCK_PHY_TX__43: 8 PC
 SG_ P2D_BUCK_PHY_TX_Byte1_43 : 0|8@1+ (1,0) [0|255] ""  DCDC
 SG_ P2D_BUCK_PHY_TX_Byte2_43 : 8|8@1+ (1,0) [0|255] ""  DCDC
 SG_ P2D_BUCK_PHY_TX_Byte3_43 : 16|8@1+ (1,0) [0|255] ""  DCDC
 SG_ P2D_BUCK_PHY_TX_Byte4_43 : 24|8@1+ (1,0) [0|255] ""  DCDC
 SG_ P2D_BUCK_PHY_TX_Byte5_43 : 32|8@1+ (1,0) [0|255] ""  DCDC
 SG_ P2D_BUCK_PHY_TX_Byte6_43 : 40|8@1+ (1,0) [0|255] ""  DCDC
 SG_ P2D_BUCK_PHY_TX_Byte7_43 : 48|8@1+ (1,0) [0|255] ""  DCDC
 SG_ P2D_BUCK_PHY_TX_Byte8_43 : 56|8@1+ (1,0) [0|255] ""  DCDC

BO_ 2149089132 P2D_BUCK_PHY_TX__44: 8 PC
 SG_ P2D_BUCK_PHY_TX_Byte1_44 : 0|8@1+ (1,0) [0|255] ""  DCDC
 SG_ P2D_BUCK_PHY_TX_Byte2_44 : 8|8@1+ (1,0) [0|255] ""  DCDC
 SG_ P2D_BUCK_PHY_TX_Byte3_44 : 16|8@1+ (1,0) [0|255] ""  DCDC
 SG_ P2D_BUCK_PHY_TX_Byte4_44 : 24|8@1+ (1,0) [0|255] ""  DCDC
 SG_ P2D_BUCK_PHY_TX_Byte5_44 : 32|8@1+ (1,0) [0|255] ""  DCDC
 SG_ P2D_BUCK_PHY_TX_Byte6_44 : 40|8@1+ (1,0) [0|255] ""  DCDC
 SG_ P2D_BUCK_PHY_TX_Byte7_44 : 48|8@1+ (1,0) [0|255] ""  DCDC
 SG_ P2D_BUCK_PHY_TX_Byte8_44 : 56|8@1+ (1,0) [0|255] ""  DCDC

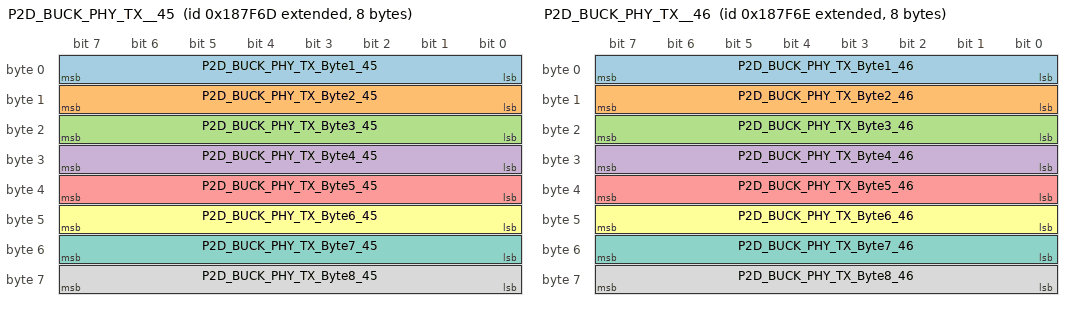
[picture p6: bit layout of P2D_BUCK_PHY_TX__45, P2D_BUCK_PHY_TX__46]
BO_ 2149089133 P2D_BUCK_PHY_TX__45: 8 PC
 SG_ P2D_BUCK_PHY_TX_Byte1_45 : 0|8@1+ (1,0) [0|255] ""  DCDC
 SG_ P2D_BUCK_PHY_TX_Byte2_45 : 8|8@1+ (1,0) [0|255] ""  DCDC
 SG_ P2D_BUCK_PHY_TX_Byte3_45 : 16|8@1+ (1,0) [0|255] ""  DCDC
 SG_ P2D_BUCK_PHY_TX_Byte4_45 : 24|8@1+ (1,0) [0|255] ""  DCDC
 SG_ P2D_BUCK_PHY_TX_Byte5_45 : 32|8@1+ (1,0) [0|255] ""  DCDC
 SG_ P2D_BUCK_PHY_TX_Byte6_45 : 40|8@1+ (1,0) [0|255] ""  DCDC
 SG_ P2D_BUCK_PHY_TX_Byte7_45 : 48|8@1+ (1,0) [0|255] ""  DCDC
 SG_ P2D_BUCK_PHY_TX_Byte8_45 : 56|8@1+ (1,0) [0|255] ""  DCDC

BO_ 2149089134 P2D_BUCK_PHY_TX__46: 8 PC
 SG_ P2D_BUCK_PHY_TX_Byte1_46 : 0|8@1+ (1,0) [0|255] ""  DCDC
 SG_ P2D_BUCK_PHY_TX_Byte2_46 : 8|8@1+ (1,0) [0|255] ""  DCDC
 SG_ P2D_BUCK_PHY_TX_Byte3_46 : 16|8@1+ (1,0) [0|255] ""  DCDC
 SG_ P2D_BUCK_PHY_TX_Byte4_46 : 24|8@1+ (1,0) [0|255] ""  DCDC
 SG_ P2D_BUCK_PHY_TX_Byte5_46 : 32|8@1+ (1,0) [0|255] ""  DCDC
 SG_ P2D_BUCK_PHY_TX_Byte6_46 : 40|8@1+ (1,0) [0|255] ""  DCDC
 SG_ P2D_BUCK_PHY_TX_Byte7_46 : 48|8@1+ (1,0) [0|255] ""  DCDC
 SG_ P2D_BUCK_PHY_TX_Byte8_46 : 56|8@1+ (1,0) [0|255] ""  DCDC

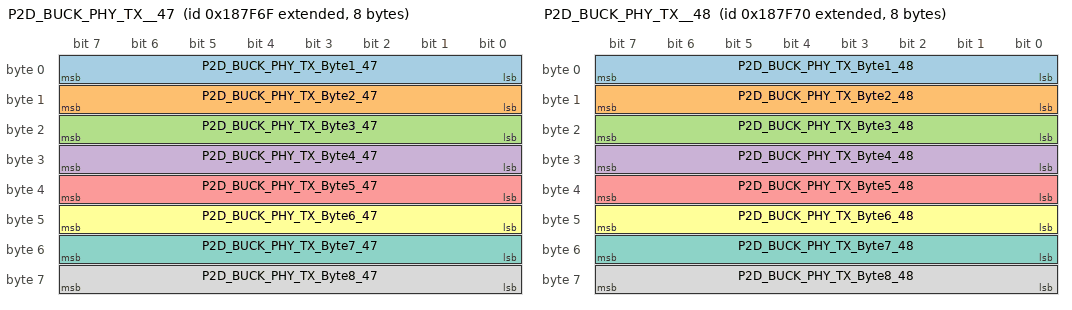
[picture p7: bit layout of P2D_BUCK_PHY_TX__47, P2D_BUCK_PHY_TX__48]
BO_ 2149089135 P2D_BUCK_PHY_TX__47: 8 PC
 SG_ P2D_BUCK_PHY_TX_Byte1_47 : 0|8@1+ (1,0) [0|255] ""  DCDC
 SG_ P2D_BUCK_PHY_TX_Byte2_47 : 8|8@1+ (1,0) [0|255] ""  DCDC
 SG_ P2D_BUCK_PHY_TX_Byte3_47 : 16|8@1+ (1,0) [0|255] ""  DCDC
 SG_ P2D_BUCK_PHY_TX_Byte4_47 : 24|8@1+ (1,0) [0|255] ""  DCDC
 SG_ P2D_BUCK_PHY_TX_Byte5_47 : 32|8@1+ (1,0) [0|255] ""  DCDC
 SG_ P2D_BUCK_PHY_TX_Byte6_47 : 40|8@1+ (1,0) [0|255] ""  DCDC
 SG_ P2D_BUCK_PHY_TX_Byte7_47 : 48|8@1+ (1,0) [0|255] ""  DCDC
 SG_ P2D_BUCK_PHY_TX_Byte8_47 : 56|8@1+ (1,0) [0|255] ""  DCDC

BO_ 2149089136 P2D_BUCK_PHY_TX__48: 8 PC
 SG_ P2D_BUCK_PHY_TX_Byte1_48 : 0|8@1+ (1,0) [0|255] ""  DCDC
 SG_ P2D_BUCK_PHY_TX_Byte2_48 : 8|8@1+ (1,0) [0|255] ""  DCDC
 SG_ P2D_BUCK_PHY_TX_Byte3_48 : 16|8@1+ (1,0) [0|255] ""  DCDC
 SG_ P2D_BUCK_PHY_TX_Byte4_48 : 24|8@1+ (1,0) [0|255] ""  DCDC
 SG_ P2D_BUCK_PHY_TX_Byte5_48 : 32|8@1+ (1,0) [0|255] ""  DCDC
 SG_ P2D_BUCK_PHY_TX_Byte6_48 : 40|8@1+ (1,0) [0|255] ""  DCDC
 SG_ P2D_BUCK_PHY_TX_Byte7_48 : 48|8@1+ (1,0) [0|255] ""  DCDC
 SG_ P2D_BUCK_PHY_TX_Byte8_48 : 56|8@1+ (1,0) [0|255] ""  DCDC

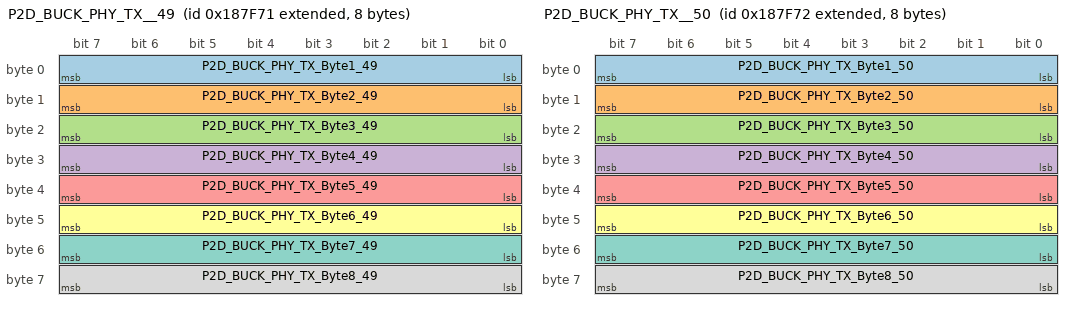
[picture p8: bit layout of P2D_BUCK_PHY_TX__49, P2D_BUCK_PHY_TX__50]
BO_ 2149089137 P2D_BUCK_PHY_TX__49: 8 PC
 SG_ P2D_BUCK_PHY_TX_Byte1_49 : 0|8@1+ (1,0) [0|255] ""  DCDC
 SG_ P2D_BUCK_PHY_TX_Byte2_49 : 8|8@1+ (1,0) [0|255] ""  DCDC
 SG_ P2D_BUCK_PHY_TX_Byte3_49 : 16|8@1+ (1,0) [0|255] ""  DCDC
 SG_ P2D_BUCK_PHY_TX_Byte4_49 : 24|8@1+ (1,0) [0|255] ""  DCDC
 SG_ P2D_BUCK_PHY_TX_Byte5_49 : 32|8@1+ (1,0) [0|255] ""  DCDC
 SG_ P2D_BUCK_PHY_TX_Byte6_49 : 40|8@1+ (1,0) [0|255] ""  DCDC
 SG_ P2D_BUCK_PHY_TX_Byte7_49 : 48|8@1+ (1,0) [0|255] ""  DCDC
 SG_ P2D_BUCK_PHY_TX_Byte8_49 : 56|8@1+ (1,0) [0|255] ""  DCDC

BO_ 2149089138 P2D_BUCK_PHY_TX__50: 8 PC
 SG_ P2D_BUCK_PHY_TX_Byte1_50 : 0|8@1+ (1,0) [0|255] ""  DCDC
 SG_ P2D_BUCK_PHY_TX_Byte2_50 : 8|8@1+ (1,0) [0|255] ""  DCDC
 SG_ P2D_BUCK_PHY_TX_Byte3_50 : 16|8@1+ (1,0) [0|255] ""  DCDC
 SG_ P2D_BUCK_PHY_TX_Byte4_50 : 24|8@1+ (1,0) [0|255] ""  DCDC
 SG_ P2D_BUCK_PHY_TX_Byte5_50 : 32|8@1+ (1,0) [0|255] ""  DCDC
 SG_ P2D_BUCK_PHY_TX_Byte6_50 : 40|8@1+ (1,0) [0|255] ""  DCDC
 SG_ P2D_BUCK_PHY_TX_Byte7_50 : 48|8@1+ (1,0) [0|255] ""  DCDC
 SG_ P2D_BUCK_PHY_TX_Byte8_50 : 56|8@1+ (1,0) [0|255] ""  DCDC

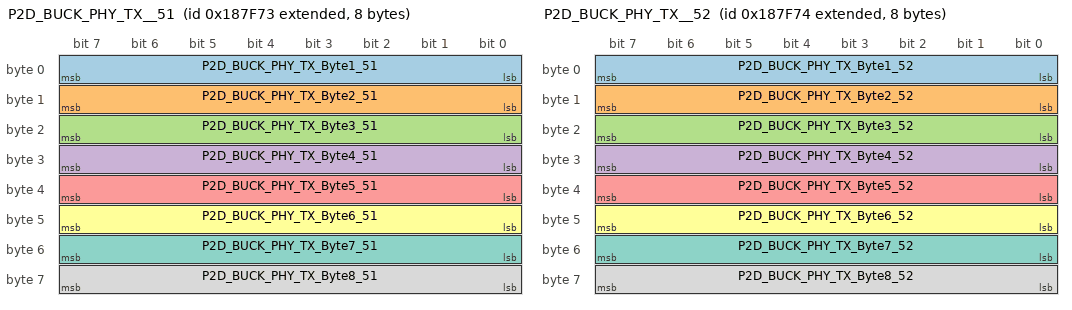
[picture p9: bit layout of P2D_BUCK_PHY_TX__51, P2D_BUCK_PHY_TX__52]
BO_ 2149089139 P2D_BUCK_PHY_TX__51: 8 PC
 SG_ P2D_BUCK_PHY_TX_Byte1_51 : 0|8@1+ (1,0) [0|255] ""  DCDC
 SG_ P2D_BUCK_PHY_TX_Byte2_51 : 8|8@1+ (1,0) [0|255] ""  DCDC
 SG_ P2D_BUCK_PHY_TX_Byte3_51 : 16|8@1+ (1,0) [0|255] ""  DCDC
 SG_ P2D_BUCK_PHY_TX_Byte4_51 : 24|8@1+ (1,0) [0|255] ""  DCDC
 SG_ P2D_BUCK_PHY_TX_Byte5_51 : 32|8@1+ (1,0) [0|255] ""  DCDC
 SG_ P2D_BUCK_PHY_TX_Byte6_51 : 40|8@1+ (1,0) [0|255] ""  DCDC
 SG_ P2D_BUCK_PHY_TX_Byte7_51 : 48|8@1+ (1,0) [0|255] ""  DCDC
 SG_ P2D_BUCK_PHY_TX_Byte8_51 : 56|8@1+ (1,0) [0|255] ""  DCDC

BO_ 2149089140 P2D_BUCK_PHY_TX__52: 8 PC
 SG_ P2D_BUCK_PHY_TX_Byte1_52 : 0|8@1+ (1,0) [0|255] ""  DCDC
 SG_ P2D_BUCK_PHY_TX_Byte2_52 : 8|8@1+ (1,0) [0|255] ""  DCDC
 SG_ P2D_BUCK_PHY_TX_Byte3_52 : 16|8@1+ (1,0) [0|255] ""  DCDC
 SG_ P2D_BUCK_PHY_TX_Byte4_52 : 24|8@1+ (1,0) [0|255] ""  DCDC
 SG_ P2D_BUCK_PHY_TX_Byte5_52 : 32|8@1+ (1,0) [0|255] ""  DCDC
 SG_ P2D_BUCK_PHY_TX_Byte6_52 : 40|8@1+ (1,0) [0|255] ""  DCDC
 SG_ P2D_BUCK_PHY_TX_Byte7_52 : 48|8@1+ (1,0) [0|255] ""  DCDC
 SG_ P2D_BUCK_PHY_TX_Byte8_52 : 56|8@1+ (1,0) [0|255] ""  DCDC

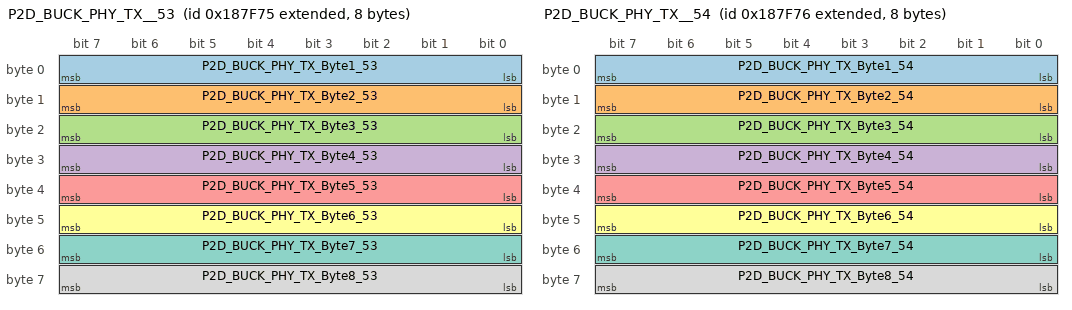
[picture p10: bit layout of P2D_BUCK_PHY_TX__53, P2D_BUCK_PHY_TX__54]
BO_ 2149089141 P2D_BUCK_PHY_TX__53: 8 PC
 SG_ P2D_BUCK_PHY_TX_Byte1_53 : 0|8@1+ (1,0) [0|255] ""  DCDC
 SG_ P2D_BUCK_PHY_TX_Byte2_53 : 8|8@1+ (1,0) [0|255] ""  DCDC
 SG_ P2D_BUCK_PHY_TX_Byte3_53 : 16|8@1+ (1,0) [0|255] ""  DCDC
 SG_ P2D_BUCK_PHY_TX_Byte4_53 : 24|8@1+ (1,0) [0|255] ""  DCDC
 SG_ P2D_BUCK_PHY_TX_Byte5_53 : 32|8@1+ (1,0) [0|255] ""  DCDC
 SG_ P2D_BUCK_PHY_TX_Byte6_53 : 40|8@1+ (1,0) [0|255] ""  DCDC
 SG_ P2D_BUCK_PHY_TX_Byte7_53 : 48|8@1+ (1,0) [0|255] ""  DCDC
 SG_ P2D_BUCK_PHY_TX_Byte8_53 : 56|8@1+ (1,0) [0|255] ""  DCDC

BO_ 2149089142 P2D_BUCK_PHY_TX__54: 8 PC
 SG_ P2D_BUCK_PHY_TX_Byte1_54 : 0|8@1+ (1,0) [0|255] ""  DCDC
 SG_ P2D_BUCK_PHY_TX_Byte2_54 : 8|8@1+ (1,0) [0|255] ""  DCDC
 SG_ P2D_BUCK_PHY_TX_Byte3_54 : 16|8@1+ (1,0) [0|255] ""  DCDC
 SG_ P2D_BUCK_PHY_TX_Byte4_54 : 24|8@1+ (1,0) [0|255] ""  DCDC
 SG_ P2D_BUCK_PHY_TX_Byte5_54 : 32|8@1+ (1,0) [0|255] ""  DCDC
 SG_ P2D_BUCK_PHY_TX_Byte6_54 : 40|8@1+ (1,0) [0|255] ""  DCDC
 SG_ P2D_BUCK_PHY_TX_Byte7_54 : 48|8@1+ (1,0) [0|255] ""  DCDC
 SG_ P2D_BUCK_PHY_TX_Byte8_54 : 56|8@1+ (1,0) [0|255] ""  DCDC

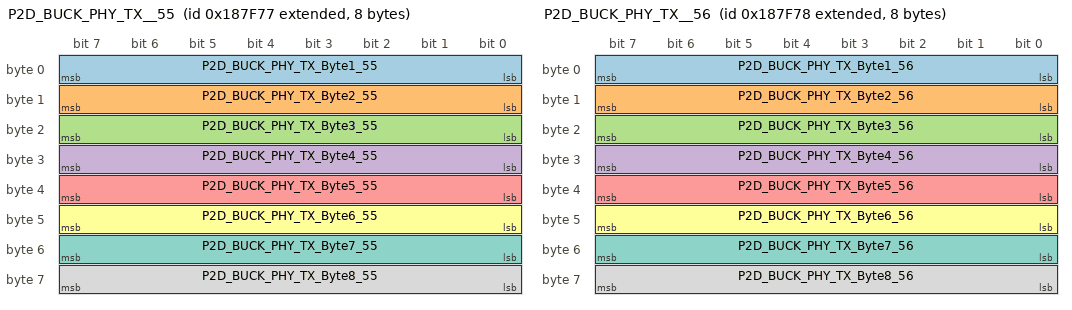
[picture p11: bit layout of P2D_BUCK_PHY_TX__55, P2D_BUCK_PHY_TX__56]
BO_ 2149089143 P2D_BUCK_PHY_TX__55: 8 PC
 SG_ P2D_BUCK_PHY_TX_Byte1_55 : 0|8@1+ (1,0) [0|255] ""  DCDC
 SG_ P2D_BUCK_PHY_TX_Byte2_55 : 8|8@1+ (1,0) [0|255] ""  DCDC
 SG_ P2D_BUCK_PHY_TX_Byte3_55 : 16|8@1+ (1,0) [0|255] ""  DCDC
 SG_ P2D_BUCK_PHY_TX_Byte4_55 : 24|8@1+ (1,0) [0|255] ""  DCDC
 SG_ P2D_BUCK_PHY_TX_Byte5_55 : 32|8@1+ (1,0) [0|255] ""  DCDC
 SG_ P2D_BUCK_PHY_TX_Byte6_55 : 40|8@1+ (1,0) [0|255] ""  DCDC
 SG_ P2D_BUCK_PHY_TX_Byte7_55 : 48|8@1+ (1,0) [0|255] ""  DCDC
 SG_ P2D_BUCK_PHY_TX_Byte8_55 : 56|8@1+ (1,0) [0|255] ""  DCDC

BO_ 2149089144 P2D_BUCK_PHY_TX__56: 8 PC
 SG_ P2D_BUCK_PHY_TX_Byte1_56 : 0|8@1+ (1,0) [0|255] ""  DCDC
 SG_ P2D_BUCK_PHY_TX_Byte2_56 : 8|8@1+ (1,0) [0|255] ""  DCDC
 SG_ P2D_BUCK_PHY_TX_Byte3_56 : 16|8@1+ (1,0) [0|255] ""  DCDC
 SG_ P2D_BUCK_PHY_TX_Byte4_56 : 24|8@1+ (1,0) [0|255] ""  DCDC
 SG_ P2D_BUCK_PHY_TX_Byte5_56 : 32|8@1+ (1,0) [0|255] ""  DCDC
 SG_ P2D_BUCK_PHY_TX_Byte6_56 : 40|8@1+ (1,0) [0|255] ""  DCDC
 SG_ P2D_BUCK_PHY_TX_Byte7_56 : 48|8@1+ (1,0) [0|255] ""  DCDC
 SG_ P2D_BUCK_PHY_TX_Byte8_56 : 56|8@1+ (1,0) [0|255] ""  DCDC

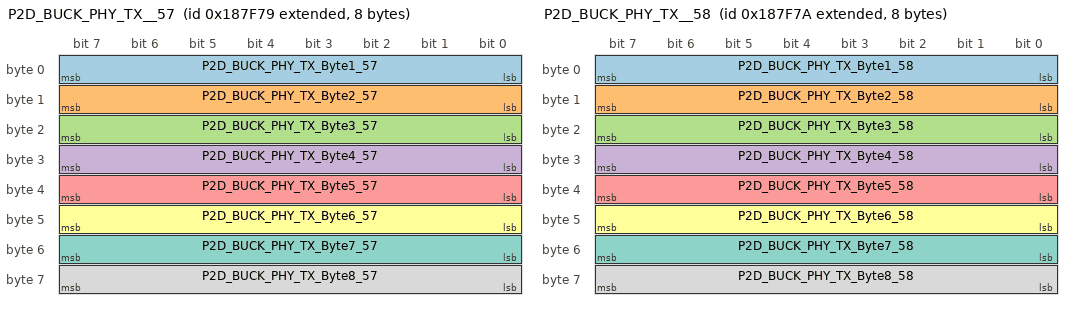
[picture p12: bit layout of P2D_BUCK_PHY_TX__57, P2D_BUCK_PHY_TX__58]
BO_ 2149089145 P2D_BUCK_PHY_TX__57: 8 PC
 SG_ P2D_BUCK_PHY_TX_Byte1_57 : 0|8@1+ (1,0) [0|255] ""  DCDC
 SG_ P2D_BUCK_PHY_TX_Byte2_57 : 8|8@1+ (1,0) [0|255] ""  DCDC
 SG_ P2D_BUCK_PHY_TX_Byte3_57 : 16|8@1+ (1,0) [0|255] ""  DCDC
 SG_ P2D_BUCK_PHY_TX_Byte4_57 : 24|8@1+ (1,0) [0|255] ""  DCDC
 SG_ P2D_BUCK_PHY_TX_Byte5_57 : 32|8@1+ (1,0) [0|255] ""  DCDC
 SG_ P2D_BUCK_PHY_TX_Byte6_57 : 40|8@1+ (1,0) [0|255] ""  DCDC
 SG_ P2D_BUCK_PHY_TX_Byte7_57 : 48|8@1+ (1,0) [0|255] ""  DCDC
 SG_ P2D_BUCK_PHY_TX_Byte8_57 : 56|8@1+ (1,0) [0|255] ""  DCDC

BO_ 2149089146 P2D_BUCK_PHY_TX__58: 8 PC
 SG_ P2D_BUCK_PHY_TX_Byte1_58 : 0|8@1+ (1,0) [0|255] ""  DCDC
 SG_ P2D_BUCK_PHY_TX_Byte2_58 : 8|8@1+ (1,0) [0|255] ""  DCDC
 SG_ P2D_BUCK_PHY_TX_Byte3_58 : 16|8@1+ (1,0) [0|255] ""  DCDC
 SG_ P2D_BUCK_PHY_TX_Byte4_58 : 24|8@1+ (1,0) [0|255] ""  DCDC
 SG_ P2D_BUCK_PHY_TX_Byte5_58 : 32|8@1+ (1,0) [0|255] ""  DCDC
 SG_ P2D_BUCK_PHY_TX_Byte6_58 : 40|8@1+ (1,0) [0|255] ""  DCDC
 SG_ P2D_BUCK_PHY_TX_Byte7_58 : 48|8@1+ (1,0) [0|255] ""  DCDC
 SG_ P2D_BUCK_PHY_TX_Byte8_58 : 56|8@1+ (1,0) [0|255] ""  DCDC

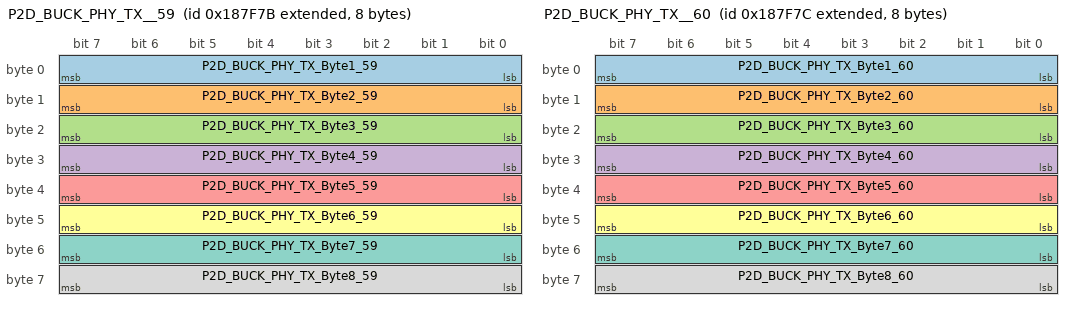
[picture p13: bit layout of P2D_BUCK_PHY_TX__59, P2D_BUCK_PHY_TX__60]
BO_ 2149089147 P2D_BUCK_PHY_TX__59: 8 PC
 SG_ P2D_BUCK_PHY_TX_Byte1_59 : 0|8@1+ (1,0) [0|255] ""  DCDC
 SG_ P2D_BUCK_PHY_TX_Byte2_59 : 8|8@1+ (1,0) [0|255] ""  DCDC
 SG_ P2D_BUCK_PHY_TX_Byte3_59 : 16|8@1+ (1,0) [0|255] ""  DCDC
 SG_ P2D_BUCK_PHY_TX_Byte4_59 : 24|8@1+ (1,0) [0|255] ""  DCDC
 SG_ P2D_BUCK_PHY_TX_Byte5_59 : 32|8@1+ (1,0) [0|255] ""  DCDC
 SG_ P2D_BUCK_PHY_TX_Byte6_59 : 40|8@1+ (1,0) [0|255] ""  DCDC
 SG_ P2D_BUCK_PHY_TX_Byte7_59 : 48|8@1+ (1,0) [0|255] ""  DCDC
 SG_ P2D_BUCK_PHY_TX_Byte8_59 : 56|8@1+ (1,0) [0|255] ""  DCDC

BO_ 2149089148 P2D_BUCK_PHY_TX__60: 8 PC
 SG_ P2D_BUCK_PHY_TX_Byte1_60 : 0|8@1+ (1,0) [0|255] ""  DCDC
 SG_ P2D_BUCK_PHY_TX_Byte2_60 : 8|8@1+ (1,0) [0|255] ""  DCDC
 SG_ P2D_BUCK_PHY_TX_Byte3_60 : 16|8@1+ (1,0) [0|255] ""  DCDC
 SG_ P2D_BUCK_PHY_TX_Byte4_60 : 24|8@1+ (1,0) [0|255] ""  DCDC
 SG_ P2D_BUCK_PHY_TX_Byte5_60 : 32|8@1+ (1,0) [0|255] ""  DCDC
 SG_ P2D_BUCK_PHY_TX_Byte6_60 : 40|8@1+ (1,0) [0|255] ""  DCDC
 SG_ P2D_BUCK_PHY_TX_Byte7_60 : 48|8@1+ (1,0) [0|255] ""  DCDC
 SG_ P2D_BUCK_PHY_TX_Byte8_60 : 56|8@1+ (1,0) [0|255] ""  DCDC

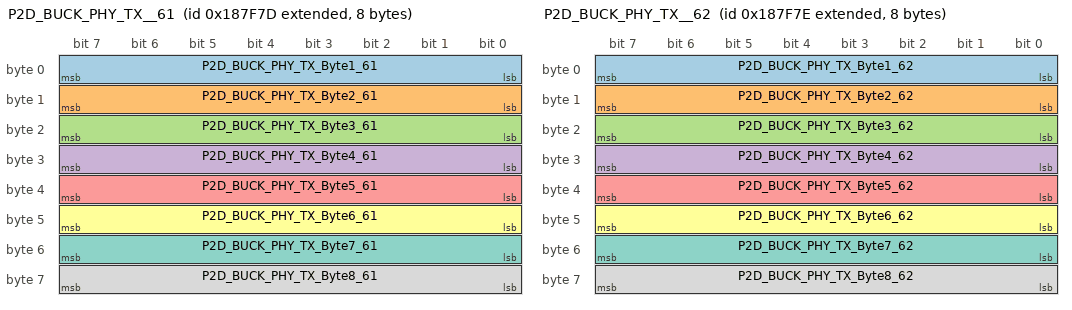
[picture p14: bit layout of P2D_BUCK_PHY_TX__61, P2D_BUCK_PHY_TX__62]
BO_ 2149089149 P2D_BUCK_PHY_TX__61: 8 PC
 SG_ P2D_BUCK_PHY_TX_Byte1_61 : 0|8@1+ (1,0) [0|255] ""  DCDC
 SG_ P2D_BUCK_PHY_TX_Byte2_61 : 8|8@1+ (1,0) [0|255] ""  DCDC
 SG_ P2D_BUCK_PHY_TX_Byte3_61 : 16|8@1+ (1,0) [0|255] ""  DCDC
 SG_ P2D_BUCK_PHY_TX_Byte4_61 : 24|8@1+ (1,0) [0|255] ""  DCDC
 SG_ P2D_BUCK_PHY_TX_Byte5_61 : 32|8@1+ (1,0) [0|255] ""  DCDC
 SG_ P2D_BUCK_PHY_TX_Byte6_61 : 40|8@1+ (1,0) [0|255] ""  DCDC
 SG_ P2D_BUCK_PHY_TX_Byte7_61 : 48|8@1+ (1,0) [0|255] ""  DCDC
 SG_ P2D_BUCK_PHY_TX_Byte8_61 : 56|8@1+ (1,0) [0|255] ""  DCDC

BO_ 2149089150 P2D_BUCK_PHY_TX__62: 8 PC
 SG_ P2D_BUCK_PHY_TX_Byte1_62 : 0|8@1+ (1,0) [0|255] ""  DCDC
 SG_ P2D_BUCK_PHY_TX_Byte2_62 : 8|8@1+ (1,0) [0|255] ""  DCDC
 SG_ P2D_BUCK_PHY_TX_Byte3_62 : 16|8@1+ (1,0) [0|255] ""  DCDC
 SG_ P2D_BUCK_PHY_TX_Byte4_62 : 24|8@1+ (1,0) [0|255] ""  DCDC
 SG_ P2D_BUCK_PHY_TX_Byte5_62 : 32|8@1+ (1,0) [0|255] ""  DCDC
 SG_ P2D_BUCK_PHY_TX_Byte6_62 : 40|8@1+ (1,0) [0|255] ""  DCDC
 SG_ P2D_BUCK_PHY_TX_Byte7_62 : 48|8@1+ (1,0) [0|255] ""  DCDC
 SG_ P2D_BUCK_PHY_TX_Byte8_62 : 56|8@1+ (1,0) [0|255] ""  DCDC

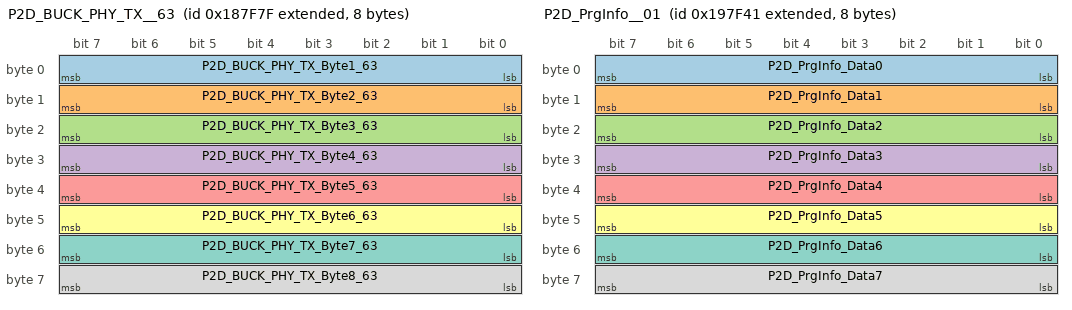
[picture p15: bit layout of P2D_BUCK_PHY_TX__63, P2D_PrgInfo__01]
BO_ 2149089151 P2D_BUCK_PHY_TX__63: 8 PC
 SG_ P2D_BUCK_PHY_TX_Byte1_63 : 0|8@1+ (1,0) [0|255] ""  DCDC
 SG_ P2D_BUCK_PHY_TX_Byte2_63 : 8|8@1+ (1,0) [0|255] ""  DCDC
 SG_ P2D_BUCK_PHY_TX_Byte3_63 : 16|8@1+ (1,0) [0|255] ""  DCDC
 SG_ P2D_BUCK_PHY_TX_Byte4_63 : 24|8@1+ (1,0) [0|255] ""  DCDC
 SG_ P2D_BUCK_PHY_TX_Byte5_63 : 32|8@1+ (1,0) [0|255] ""  DCDC
 SG_ P2D_BUCK_PHY_TX_Byte6_63 : 40|8@1+ (1,0) [0|255] ""  DCDC
 SG_ P2D_BUCK_PHY_TX_Byte7_63 : 48|8@1+ (1,0) [0|255] ""  DCDC
 SG_ P2D_BUCK_PHY_TX_Byte8_63 : 56|8@1+ (1,0) [0|255] ""  DCDC

BO_ 2149154625 P2D_PrgInfo__01: 8 PC
 SG_ P2D_PrgInfo_Data0 : 0|8@1+ (1,0) [0|255] ""  DCDC
 SG_ P2D_PrgInfo_Data1 : 8|8@1+ (1,0) [0|255] ""  DCDC
 SG_ P2D_PrgInfo_Data2 : 16|8@1+ (1,0) [0|255] ""  DCDC
 SG_ P2D_PrgInfo_Data3 : 24|8@1+ (1,0) [0|255] ""  DCDC
 SG_ P2D_PrgInfo_Data4 : 32|8@1+ (1,0) [0|255] ""  DCDC
 SG_ P2D_PrgInfo_Data5 : 40|8@1+ (1,0) [0|255] ""  DCDC
 SG_ P2D_PrgInfo_Data6 : 48|8@1+ (1,0) [0|255] ""  DCDC
 SG_ P2D_PrgInfo_Data7 : 56|8@1+ (1,0) [0|255] ""  DCDC

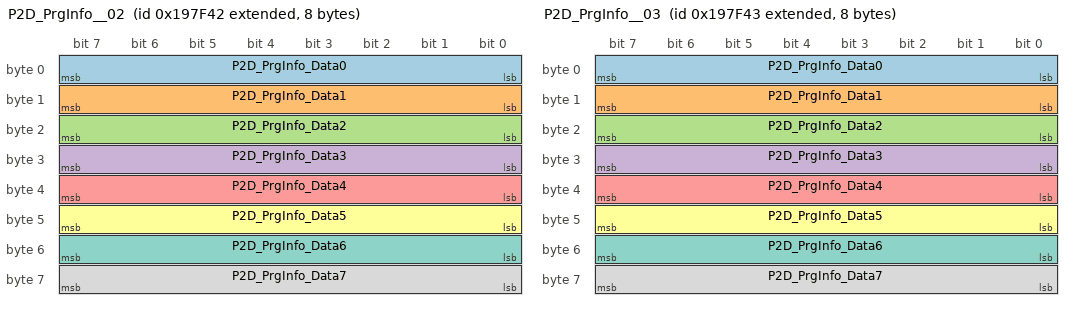
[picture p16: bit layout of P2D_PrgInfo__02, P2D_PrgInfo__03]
BO_ 2149154626 P2D_PrgInfo__02: 8 PC
 SG_ P2D_PrgInfo_Data0 : 0|8@1+ (1,0) [0|255] ""  DCDC
 SG_ P2D_PrgInfo_Data1 : 8|8@1+ (1,0) [0|255] ""  DCDC
 SG_ P2D_PrgInfo_Data2 : 16|8@1+ (1,0) [0|255] ""  DCDC
 SG_ P2D_PrgInfo_Data3 : 24|8@1+ (1,0) [0|255] ""  DCDC
 SG_ P2D_PrgInfo_Data4 : 32|8@1+ (1,0) [0|255] ""  DCDC
 SG_ P2D_PrgInfo_Data5 : 40|8@1+ (1,0) [0|255] ""  DCDC
 SG_ P2D_PrgInfo_Data6 : 48|8@1+ (1,0) [0|255] ""  DCDC
 SG_ P2D_PrgInfo_Data7 : 56|8@1+ (1,0) [0|255] ""  DCDC

BO_ 2149154627 P2D_PrgInfo__03: 8 PC
 SG_ P2D_PrgInfo_Data0 : 0|8@1+ (1,0) [0|255] ""  DCDC
 SG_ P2D_PrgInfo_Data1 : 8|8@1+ (1,0) [0|255] ""  DCDC
 SG_ P2D_PrgInfo_Data2 : 16|8@1+ (1,0) [0|255] ""  DCDC
 SG_ P2D_PrgInfo_Data3 : 24|8@1+ (1,0) [0|255] ""  DCDC
 SG_ P2D_PrgInfo_Data4 : 32|8@1+ (1,0) [0|255] ""  DCDC
 SG_ P2D_PrgInfo_Data5 : 40|8@1+ (1,0) [0|255] ""  DCDC
 SG_ P2D_PrgInfo_Data6 : 48|8@1+ (1,0) [0|255] ""  DCDC
 SG_ P2D_PrgInfo_Data7 : 56|8@1+ (1,0) [0|255] ""  DCDC

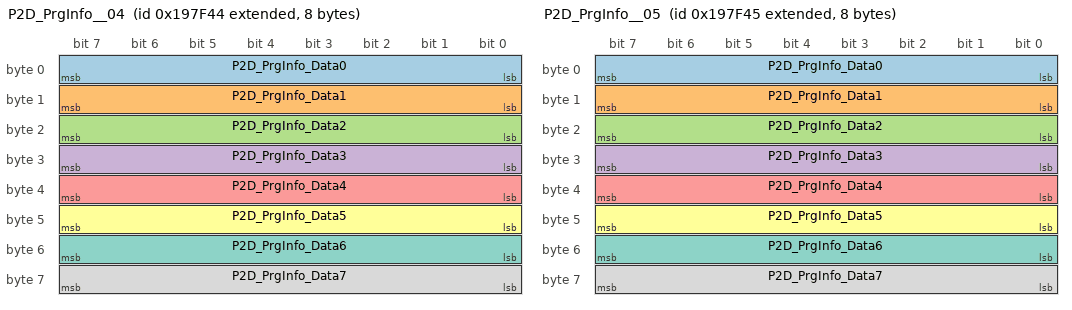
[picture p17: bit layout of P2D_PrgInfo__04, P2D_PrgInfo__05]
BO_ 2149154628 P2D_PrgInfo__04: 8 PC
 SG_ P2D_PrgInfo_Data0 : 0|8@1+ (1,0) [0|255] ""  DCDC
 SG_ P2D_PrgInfo_Data1 : 8|8@1+ (1,0) [0|255] ""  DCDC
 SG_ P2D_PrgInfo_Data2 : 16|8@1+ (1,0) [0|255] ""  DCDC
 SG_ P2D_PrgInfo_Data3 : 24|8@1+ (1,0) [0|255] ""  DCDC
 SG_ P2D_PrgInfo_Data4 : 32|8@1+ (1,0) [0|255] ""  DCDC
 SG_ P2D_PrgInfo_Data5 : 40|8@1+ (1,0) [0|255] ""  DCDC
 SG_ P2D_PrgInfo_Data6 : 48|8@1+ (1,0) [0|255] ""  DCDC
 SG_ P2D_PrgInfo_Data7 : 56|8@1+ (1,0) [0|255] ""  DCDC

BO_ 2149154629 P2D_PrgInfo__05: 8 PC
 SG_ P2D_PrgInfo_Data0 : 0|8@1+ (1,0) [0|255] ""  DCDC
 SG_ P2D_PrgInfo_Data1 : 8|8@1+ (1,0) [0|255] ""  DCDC
 SG_ P2D_PrgInfo_Data2 : 16|8@1+ (1,0) [0|255] ""  DCDC
 SG_ P2D_PrgInfo_Data3 : 24|8@1+ (1,0) [0|255] ""  DCDC
 SG_ P2D_PrgInfo_Data4 : 32|8@1+ (1,0) [0|255] ""  DCDC
 SG_ P2D_PrgInfo_Data5 : 40|8@1+ (1,0) [0|255] ""  DCDC
 SG_ P2D_PrgInfo_Data6 : 48|8@1+ (1,0) [0|255] ""  DCDC
 SG_ P2D_PrgInfo_Data7 : 56|8@1+ (1,0) [0|255] ""  DCDC

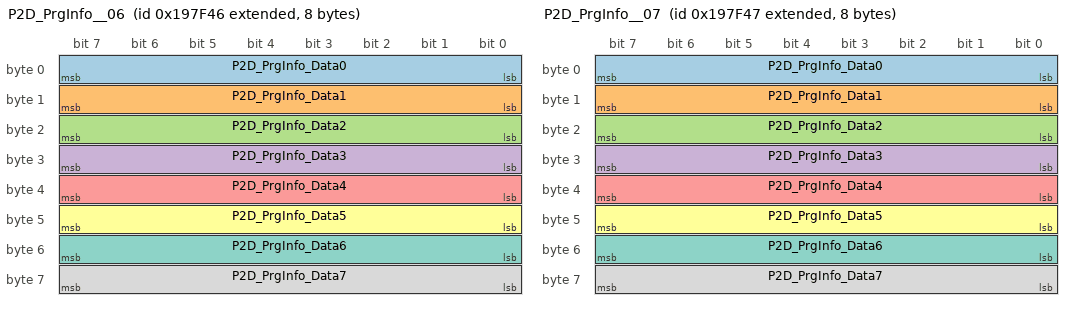
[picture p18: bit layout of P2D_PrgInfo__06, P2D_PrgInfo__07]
BO_ 2149154630 P2D_PrgInfo__06: 8 PC
 SG_ P2D_PrgInfo_Data0 : 0|8@1+ (1,0) [0|255] ""  DCDC
 SG_ P2D_PrgInfo_Data1 : 8|8@1+ (1,0) [0|255] ""  DCDC
 SG_ P2D_PrgInfo_Data2 : 16|8@1+ (1,0) [0|255] ""  DCDC
 SG_ P2D_PrgInfo_Data3 : 24|8@1+ (1,0) [0|255] ""  DCDC
 SG_ P2D_PrgInfo_Data4 : 32|8@1+ (1,0) [0|255] ""  DCDC
 SG_ P2D_PrgInfo_Data5 : 40|8@1+ (1,0) [0|255] ""  DCDC
 SG_ P2D_PrgInfo_Data6 : 48|8@1+ (1,0) [0|255] ""  DCDC
 SG_ P2D_PrgInfo_Data7 : 56|8@1+ (1,0) [0|255] ""  DCDC

BO_ 2149154631 P2D_PrgInfo__07: 8 PC
 SG_ P2D_PrgInfo_Data0 : 0|8@1+ (1,0) [0|255] ""  DCDC
 SG_ P2D_PrgInfo_Data1 : 8|8@1+ (1,0) [0|255] ""  DCDC
 SG_ P2D_PrgInfo_Data2 : 16|8@1+ (1,0) [0|255] ""  DCDC
 SG_ P2D_PrgInfo_Data3 : 24|8@1+ (1,0) [0|255] ""  DCDC
 SG_ P2D_PrgInfo_Data4 : 32|8@1+ (1,0) [0|255] ""  DCDC
 SG_ P2D_PrgInfo_Data5 : 40|8@1+ (1,0) [0|255] ""  DCDC
 SG_ P2D_PrgInfo_Data6 : 48|8@1+ (1,0) [0|255] ""  DCDC
 SG_ P2D_PrgInfo_Data7 : 56|8@1+ (1,0) [0|255] ""  DCDC

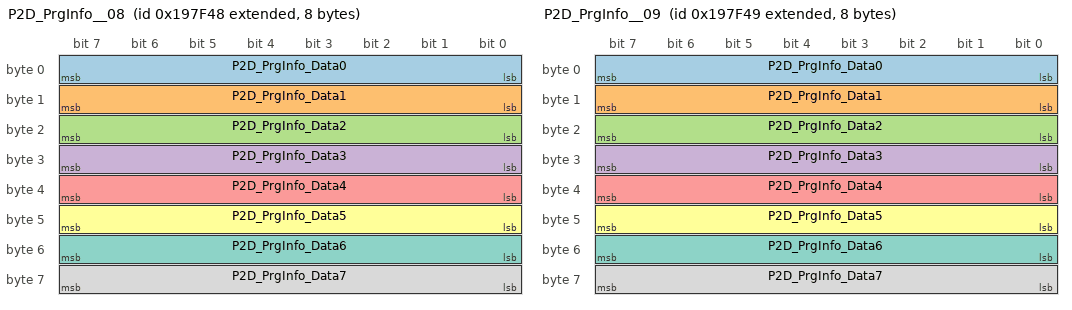
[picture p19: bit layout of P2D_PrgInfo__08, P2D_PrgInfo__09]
BO_ 2149154632 P2D_PrgInfo__08: 8 PC
 SG_ P2D_PrgInfo_Data0 : 0|8@1+ (1,0) [0|255] ""  DCDC
 SG_ P2D_PrgInfo_Data1 : 8|8@1+ (1,0) [0|255] ""  DCDC
 SG_ P2D_PrgInfo_Data2 : 16|8@1+ (1,0) [0|255] ""  DCDC
 SG_ P2D_PrgInfo_Data3 : 24|8@1+ (1,0) [0|255] ""  DCDC
 SG_ P2D_PrgInfo_Data4 : 32|8@1+ (1,0) [0|255] ""  DCDC
 SG_ P2D_PrgInfo_Data5 : 40|8@1+ (1,0) [0|255] ""  DCDC
 SG_ P2D_PrgInfo_Data6 : 48|8@1+ (1,0) [0|255] ""  DCDC
 SG_ P2D_PrgInfo_Data7 : 56|8@1+ (1,0) [0|255] ""  DCDC

BO_ 2149154633 P2D_PrgInfo__09: 8 PC
 SG_ P2D_PrgInfo_Data0 : 0|8@1+ (1,0) [0|255] ""  DCDC
 SG_ P2D_PrgInfo_Data1 : 8|8@1+ (1,0) [0|255] ""  DCDC
 SG_ P2D_PrgInfo_Data2 : 16|8@1+ (1,0) [0|255] ""  DCDC
 SG_ P2D_PrgInfo_Data3 : 24|8@1+ (1,0) [0|255] ""  DCDC
 SG_ P2D_PrgInfo_Data4 : 32|8@1+ (1,0) [0|255] ""  DCDC
 SG_ P2D_PrgInfo_Data5 : 40|8@1+ (1,0) [0|255] ""  DCDC
 SG_ P2D_PrgInfo_Data6 : 48|8@1+ (1,0) [0|255] ""  DCDC
 SG_ P2D_PrgInfo_Data7 : 56|8@1+ (1,0) [0|255] ""  DCDC

BO_ 2149154634 P2D_PrgInfo__10: 8 PC
 SG_ P2D_PrgInfo_Data0 : 0|8@1+ (1,0) [0|255] ""  DCDC
 SG_ P2D_PrgInfo_Data1 : 8|8@1+ (1,0) [0|255] ""  DCDC
 SG_ P2D_PrgInfo_Data2 : 16|8@1+ (1,0) [0|255] ""  DCDC
 SG_ P2D_PrgInfo_Data3 : 24|8@1+ (1,0) [0|255] ""  DCDC
 SG_ P2D_PrgInfo_Data4 : 32|8@1+ (1,0) [0|255] ""  DCDC
 SG_ P2D_PrgInfo_Data5 : 40|8@1+ (1,0) [0|255] ""  DCDC
 SG_ P2D_PrgInfo_Data6 : 48|8@1+ (1,0) [0|255] ""  DCDC
 SG_ P2D_PrgInfo_Data7 : 56|8@1+ (1,0) [0|255] ""  DCDC

BO_ 2149154635 P2D_PrgInfo__11: 8 PC
 SG_ P2D_PrgInfo_Data0 : 0|8@1+ (1,0) [0|255] ""  DCDC
 SG_ P2D_PrgInfo_Data1 : 8|8@1+ (1,0) [0|255] ""  DCDC
 SG_ P2D_PrgInfo_Data2 : 16|8@1+ (1,0) [0|255] ""  DCDC
 SG_ P2D_PrgInfo_Data3 : 24|8@1+ (1,0) [0|255] ""  DCDC
 SG_ P2D_PrgInfo_Data4 : 32|8@1+ (1,0) [0|255] ""  DCDC
 SG_ P2D_PrgInfo_Data5 : 40|8@1+ (1,0) [0|255] ""  DCDC
 SG_ P2D_PrgInfo_Data6 : 48|8@1+ (1,0) [0|255] ""  DCDC
 SG_ P2D_PrgInfo_Data7 : 56|8@1+ (1,0) [0|255] ""  DCDC

BO_ 2149154636 P2D_PrgInfo__12: 8 PC
 SG_ P2D_PrgInfo_Data0 : 0|8@1+ (1,0) [0|255] ""  DCDC
 SG_ P2D_PrgInfo_Data1 : 8|8@1+ (1,0) [0|255] ""  DCDC
 SG_ P2D_PrgInfo_Data2 : 16|8@1+ (1,0) [0|255] ""  DCDC
 SG_ P2D_PrgInfo_Data3 : 24|8@1+ (1,0) [0|255] ""  DCDC
 SG_ P2D_PrgInfo_Data4 : 32|8@1+ (1,0) [0|255] ""  DCDC
 SG_ P2D_PrgInfo_Data5 : 40|8@1+ (1,0) [0|255] ""  DCDC
 SG_ P2D_PrgInfo_Data6 : 48|8@1+ (1,0) [0|255] ""  DCDC
 SG_ P2D_PrgInfo_Data7 : 56|8@1+ (1,0) [0|255] ""  DCDC

BO_ 2149154637 P2D_PrgInfo__13: 8 PC
 SG_ P2D_PrgInfo_Data0 : 0|8@1+ (1,0) [0|255] ""  DCDC
 SG_ P2D_PrgInfo_Data1 : 8|8@1+ (1,0) [0|255] ""  DCDC
 SG_ P2D_PrgInfo_Data2 : 16|8@1+ (1,0) [0|255] ""  DCDC
 SG_ P2D_PrgInfo_Data3 : 24|8@1+ (1,0) [0|255] ""  DCDC
 SG_ P2D_PrgInfo_Data4 : 32|8@1+ (1,0) [0|255] ""  DCDC
 SG_ P2D_PrgInfo_Data5 : 40|8@1+ (1,0) [0|255] ""  DCDC
 SG_ P2D_PrgInfo_Data6 : 48|8@1+ (1,0) [0|255] ""  DCDC
 SG_ P2D_PrgInfo_Data7 : 56|8@1+ (1,0) [0|255] ""  DCDC

BO_ 2149154638 P2D_PrgInfo__14: 8 PC
 SG_ P2D_PrgInfo_Data0 : 0|8@1+ (1,0) [0|255] ""  DCDC
 SG_ P2D_PrgInfo_Data1 : 8|8@1+ (1,0) [0|255] ""  DCDC
 SG_ P2D_PrgInfo_Data2 : 16|8@1+ (1,0) [0|255] ""  DCDC
 SG_ P2D_PrgInfo_Data3 : 24|8@1+ (1,0) [0|255] ""  DCDC
 SG_ P2D_PrgInfo_Data4 : 32|8@1+ (1,0) [0|255] ""  DCDC
 SG_ P2D_PrgInfo_Data5 : 40|8@1+ (1,0) [0|255] ""  DCDC
 SG_ P2D_PrgInfo_Data6 : 48|8@1+ (1,0) [0|255] ""  DCDC
 SG_ P2D_PrgInfo_Data7 : 56|8@1+ (1,0) [0|255] ""  DCDC

BO_ 2149154639 P2D_PrgInfo__15: 8 PC
 SG_ P2D_PrgInfo_Data0 : 0|8@1+ (1,0) [0|255] ""  DCDC
 SG_ P2D_PrgInfo_Data1 : 8|8@1+ (1,0) [0|255] ""  DCDC
 SG_ P2D_PrgInfo_Data2 : 16|8@1+ (1,0) [0|255] ""  DCDC
 SG_ P2D_PrgInfo_Data3 : 24|8@1+ (1,0) [0|255] ""  DCDC
 SG_ P2D_PrgInfo_Data4 : 32|8@1+ (1,0) [0|255] ""  DCDC
 SG_ P2D_PrgInfo_Data5 : 40|8@1+ (1,0) [0|255] ""  DCDC
 SG_ P2D_PrgInfo_Data6 : 48|8@1+ (1,0) [0|255] ""  DCDC
 SG_ P2D_PrgInfo_Data7 : 56|8@1+ (1,0) [0|255] ""  DCDC

BO_ 2149154640 P2D_PrgInfo__16: 8 PC
 SG_ P2D_PrgInfo_Data0 : 0|8@1+ (1,0) [0|255] ""  DCDC
 SG_ P2D_PrgInfo_Data1 : 8|8@1+ (1,0) [0|255] ""  DCDC
 SG_ P2D_PrgInfo_Data2 : 16|8@1+ (1,0) [0|255] ""  DCDC
 SG_ P2D_PrgInfo_Data3 : 24|8@1+ (1,0) [0|255] ""  DCDC
 SG_ P2D_PrgInfo_Data4 : 32|8@1+ (1,0) [0|255] ""  DCDC
 SG_ P2D_PrgInfo_Data5 : 40|8@1+ (1,0) [0|255] ""  DCDC
 SG_ P2D_PrgInfo_Data6 : 48|8@1+ (1,0) [0|255] ""  DCDC
 SG_ P2D_PrgInfo_Data7 : 56|8@1+ (1,0) [0|255] ""  DCDC

BO_ 2149154641 P2D_PrgInfo__17: 8 PC
 SG_ P2D_PrgInfo_Data0 : 0|8@1+ (1,0) [0|255] ""  DCDC
 SG_ P2D_PrgInfo_Data1 : 8|8@1+ (1,0) [0|255] ""  DCDC
 SG_ P2D_PrgInfo_Data2 : 16|8@1+ (1,0) [0|255] ""  DCDC
 SG_ P2D_PrgInfo_Data3 : 24|8@1+ (1,0) [0|255] ""  DCDC
 SG_ P2D_PrgInfo_Data4 : 32|8@1+ (1,0) [0|255] ""  DCDC
 SG_ P2D_PrgInfo_Data5 : 40|8@1+ (1,0) [0|255] ""  DCDC
 SG_ P2D_PrgInfo_Data6 : 48|8@1+ (1,0) [0|255] ""  DCDC
 SG_ P2D_PrgInfo_Data7 : 56|8@1+ (1,0) [0|255] ""  DCDC

BO_ 2149154642 P2D_PrgInfo__18: 8 PC
 SG_ P2D_PrgInfo_Data0 : 0|8@1+ (1,0) [0|255] ""  DCDC
 SG_ P2D_PrgInfo_Data1 : 8|8@1+ (1,0) [0|255] ""  DCDC
 SG_ P2D_PrgInfo_Data2 : 16|8@1+ (1,0) [0|255] ""  DCDC
 SG_ P2D_PrgInfo_Data3 : 24|8@1+ (1,0) [0|255] ""  DCDC
 SG_ P2D_PrgInfo_Data4 : 32|8@1+ (1,0) [0|255] ""  DCDC
 SG_ P2D_PrgInfo_Data5 : 40|8@1+ (1,0) [0|255] ""  DCDC
 SG_ P2D_PrgInfo_Data6 : 48|8@1+ (1,0) [0|255] ""  DCDC
 SG_ P2D_PrgInfo_Data7 : 56|8@1+ (1,0) [0|255] ""  DCDC

BO_ 2149154643 P2D_PrgInfo__19: 8 PC
 SG_ P2D_PrgInfo_Data0 : 0|8@1+ (1,0) [0|255] ""  DCDC
 SG_ P2D_PrgInfo_Data1 : 8|8@1+ (1,0) [0|255] ""  DCDC
 SG_ P2D_PrgInfo_Data2 : 16|8@1+ (1,0) [0|255] ""  DCDC
 SG_ P2D_PrgInfo_Data3 : 24|8@1+ (1,0) [0|255] ""  DCDC
 SG_ P2D_PrgInfo_Data4 : 32|8@1+ (1,0) [0|255] ""  DCDC
 SG_ P2D_PrgInfo_Data5 : 40|8@1+ (1,0) [0|255] ""  DCDC
 SG_ P2D_PrgInfo_Data6 : 48|8@1+ (1,0) [0|255] ""  DCDC
 SG_ P2D_PrgInfo_Data7 : 56|8@1+ (1,0) [0|255] ""  DCDC

BO_ 2149154644 P2D_PrgInfo__20: 8 PC
 SG_ P2D_PrgInfo_Data0 : 0|8@1+ (1,0) [0|255] ""  DCDC
 SG_ P2D_PrgInfo_Data1 : 8|8@1+ (1,0) [0|255] ""  DCDC
 SG_ P2D_PrgInfo_Data2 : 16|8@1+ (1,0) [0|255] ""  DCDC
 SG_ P2D_PrgInfo_Data3 : 24|8@1+ (1,0) [0|255] ""  DCDC
 SG_ P2D_PrgInfo_Data4 : 32|8@1+ (1,0) [0|255] ""  DCDC
 SG_ P2D_PrgInfo_Data5 : 40|8@1+ (1,0) [0|255] ""  DCDC
 SG_ P2D_PrgInfo_Data6 : 48|8@1+ (1,0) [0|255] ""  DCDC
 SG_ P2D_PrgInfo_Data7 : 56|8@1+ (1,0) [0|255] ""  DCDC

BO_ 2149154645 P2D_PrgInfo__21: 8 PC
 SG_ P2D_PrgInfo_Data0 : 0|8@1+ (1,0) [0|255] ""  DCDC
 SG_ P2D_PrgInfo_Data1 : 8|8@1+ (1,0) [0|255] ""  DCDC
 SG_ P2D_PrgInfo_Data2 : 16|8@1+ (1,0) [0|255] ""  DCDC
 SG_ P2D_PrgInfo_Data3 : 24|8@1+ (1,0) [0|255] ""  DCDC
 SG_ P2D_PrgInfo_Data4 : 32|8@1+ (1,0) [0|255] ""  DCDC
 SG_ P2D_PrgInfo_Data5 : 40|8@1+ (1,0) [0|255] ""  DCDC
 SG_ P2D_PrgInfo_Data6 : 48|8@1+ (1,0) [0|255] ""  DCDC
 SG_ P2D_PrgInfo_Data7 : 56|8@1+ (1,0) [0|255] ""  DCDC

BO_ 2149154646 P2D_PrgInfo__22: 8 PC
 SG_ P2D_PrgInfo_Data0 : 0|8@1+ (1,0) [0|255] ""  DCDC
 SG_ P2D_PrgInfo_Data1 : 8|8@1+ (1,0) [0|255] ""  DCDC
 SG_ P2D_PrgInfo_Data2 : 16|8@1+ (1,0) [0|255] ""  DCDC
 SG_ P2D_PrgInfo_Data3 : 24|8@1+ (1,0) [0|255] ""  DCDC
 SG_ P2D_PrgInfo_Data4 : 32|8@1+ (1,0) [0|255] ""  DCDC
 SG_ P2D_PrgInfo_Data5 : 40|8@1+ (1,0) [0|255] ""  DCDC
 SG_ P2D_PrgInfo_Data6 : 48|8@1+ (1,0) [0|255] ""  DCDC
 SG_ P2D_PrgInfo_Data7 : 56|8@1+ (1,0) [0|255] ""  DCDC

BO_ 2149154647 P2D_PrgInfo__23: 8 PC
 SG_ P2D_PrgInfo_Data0 : 0|8@1+ (1,0) [0|255] ""  DCDC
 SG_ P2D_PrgInfo_Data1 : 8|8@1+ (1,0) [0|255] ""  DCDC
 SG_ P2D_PrgInfo_Data2 : 16|8@1+ (1,0) [0|255] ""  DCDC
 SG_ P2D_PrgInfo_Data3 : 24|8@1+ (1,0) [0|255] ""  DCDC
 SG_ P2D_PrgInfo_Data4 : 32|8@1+ (1,0) [0|255] ""  DCDC
 SG_ P2D_PrgInfo_Data5 : 40|8@1+ (1,0) [0|255] ""  DCDC
 SG_ P2D_PrgInfo_Data6 : 48|8@1+ (1,0) [0|255] ""  DCDC
 SG_ P2D_PrgInfo_Data7 : 56|8@1+ (1,0) [0|255] ""  DCDC

BO_ 2149154648 P2D_PrgInfo__24: 8 PC
 SG_ P2D_PrgInfo_Data0 : 0|8@1+ (1,0) [0|255] ""  DCDC
 SG_ P2D_PrgInfo_Data1 : 8|8@1+ (1,0) [0|255] ""  DCDC
 SG_ P2D_PrgInfo_Data2 : 16|8@1+ (1,0) [0|255] ""  DCDC
 SG_ P2D_PrgInfo_Data3 : 24|8@1+ (1,0) [0|255] ""  DCDC
 SG_ P2D_PrgInfo_Data4 : 32|8@1+ (1,0) [0|255] ""  DCDC
 SG_ P2D_PrgInfo_Data5 : 40|8@1+ (1,0) [0|255] ""  DCDC
 SG_ P2D_PrgInfo_Data6 : 48|8@1+ (1,0) [0|255] ""  DCDC
 SG_ P2D_PrgInfo_Data7 : 56|8@1+ (1,0) [0|255] ""  DCDC

BO_ 2149154649 P2D_PrgInfo__25: 8 PC
 SG_ P2D_PrgInfo_Data0 : 0|8@1+ (1,0) [0|255] ""  DCDC
 SG_ P2D_PrgInfo_Data1 : 8|8@1+ (1,0) [0|255] ""  DCDC
 SG_ P2D_PrgInfo_Data2 : 16|8@1+ (1,0) [0|255] ""  DCDC
 SG_ P2D_PrgInfo_Data3 : 24|8@1+ (1,0) [0|255] ""  DCDC
 SG_ P2D_PrgInfo_Data4 : 32|8@1+ (1,0) [0|255] ""  DCDC
 SG_ P2D_PrgInfo_Data5 : 40|8@1+ (1,0) [0|255] ""  DCDC
 SG_ P2D_PrgInfo_Data6 : 48|8@1+ (1,0) [0|255] ""  DCDC
 SG_ P2D_PrgInfo_Data7 : 56|8@1+ (1,0) [0|255] ""  DCDC

BO_ 2149154650 P2D_PrgInfo__26: 8 PC
 SG_ P2D_PrgInfo_Data0 : 0|8@1+ (1,0) [0|255] ""  DCDC
 SG_ P2D_PrgInfo_Data1 : 8|8@1+ (1,0) [0|255] ""  DCDC
 SG_ P2D_PrgInfo_Data2 : 16|8@1+ (1,0) [0|255] ""  DCDC
 SG_ P2D_PrgInfo_Data3 : 24|8@1+ (1,0) [0|255] ""  DCDC
 SG_ P2D_PrgInfo_Data4 : 32|8@1+ (1,0) [0|255] ""  DCDC
 SG_ P2D_PrgInfo_Data5 : 40|8@1+ (1,0) [0|255] ""  DCDC
 SG_ P2D_PrgInfo_Data6 : 48|8@1+ (1,0) [0|255] ""  DCDC
 SG_ P2D_PrgInfo_Data7 : 56|8@1+ (1,0) [0|255] ""  DCDC

BO_ 2149154651 P2D_PrgInfo__27: 8 PC
 SG_ P2D_PrgInfo_Data0 : 0|8@1+ (1,0) [0|255] ""  DCDC
 SG_ P2D_PrgInfo_Data1 : 8|8@1+ (1,0) [0|255] ""  DCDC
 SG_ P2D_PrgInfo_Data2 : 16|8@1+ (1,0) [0|255] ""  DCDC
 SG_ P2D_PrgInfo_Data3 : 24|8@1+ (1,0) [0|255] ""  DCDC
 SG_ P2D_PrgInfo_Data4 : 32|8@1+ (1,0) [0|255] ""  DCDC
 SG_ P2D_PrgInfo_Data5 : 40|8@1+ (1,0) [0|255] ""  DCDC
 SG_ P2D_PrgInfo_Data6 : 48|8@1+ (1,0) [0|255] ""  DCDC
 SG_ P2D_PrgInfo_Data7 : 56|8@1+ (1,0) [0|255] ""  DCDC

BO_ 2149154652 P2D_PrgInfo__28: 8 PC
 SG_ P2D_PrgInfo_Data0 : 0|8@1+ (1,0) [0|255] ""  DCDC
 SG_ P2D_PrgInfo_Data1 : 8|8@1+ (1,0) [0|255] ""  DCDC
 SG_ P2D_PrgInfo_Data2 : 16|8@1+ (1,0) [0|255] ""  DCDC
 SG_ P2D_PrgInfo_Data3 : 24|8@1+ (1,0) [0|255] ""  DCDC
 SG_ P2D_PrgInfo_Data4 : 32|8@1+ (1,0) [0|255] ""  DCDC
 SG_ P2D_PrgInfo_Data5 : 40|8@1+ (1,0) [0|255] ""  DCDC
 SG_ P2D_PrgInfo_Data6 : 48|8@1+ (1,0) [0|255] ""  DCDC
 SG_ P2D_PrgInfo_Data7 : 56|8@1+ (1,0) [0|255] ""  DCDC

BO_ 2149154653 P2D_PrgInfo__29: 8 PC
 SG_ P2D_PrgInfo_Data0 : 0|8@1+ (1,0) [0|255] ""  DCDC
 SG_ P2D_PrgInfo_Data1 : 8|8@1+ (1,0) [0|255] ""  DCDC
 SG_ P2D_PrgInfo_Data2 : 16|8@1+ (1,0) [0|255] ""  DCDC
 SG_ P2D_PrgInfo_Data3 : 24|8@1+ (1,0) [0|255] ""  DCDC
 SG_ P2D_PrgInfo_Data4 : 32|8@1+ (1,0) [0|255] ""  DCDC
 SG_ P2D_PrgInfo_Data5 : 40|8@1+ (1,0) [0|255] ""  DCDC
 SG_ P2D_PrgInfo_Data6 : 48|8@1+ (1,0) [0|255] ""  DCDC
 SG_ P2D_PrgInfo_Data7 : 56|8@1+ (1,0) [0|255] ""  DCDC

BO_ 2149154654 P2D_PrgInfo__30: 8 PC
 SG_ P2D_PrgInfo_Data0 : 0|8@1+ (1,0) [0|255] ""  DCDC
 SG_ P2D_PrgInfo_Data1 : 8|8@1+ (1,0) [0|255] ""  DCDC
 SG_ P2D_PrgInfo_Data2 : 16|8@1+ (1,0) [0|255] ""  DCDC
 SG_ P2D_PrgInfo_Data3 : 24|8@1+ (1,0) [0|255] ""  DCDC
 SG_ P2D_PrgInfo_Data4 : 32|8@1+ (1,0) [0|255] ""  DCDC
 SG_ P2D_PrgInfo_Data5 : 40|8@1+ (1,0) [0|255] ""  DCDC
 SG_ P2D_PrgInfo_Data6 : 48|8@1+ (1,0) [0|255] ""  DCDC
 SG_ P2D_PrgInfo_Data7 : 56|8@1+ (1,0) [0|255] ""  DCDC

BO_ 2149154655 P2D_PrgInfo__31: 8 PC
 SG_ P2D_PrgInfo_Data0 : 0|8@1+ (1,0) [0|255] ""  DCDC
 SG_ P2D_PrgInfo_Data1 : 8|8@1+ (1,0) [0|255] ""  DCDC
 SG_ P2D_PrgInfo_Data2 : 16|8@1+ (1,0) [0|255] ""  DCDC
 SG_ P2D_PrgInfo_Data3 : 24|8@1+ (1,0) [0|255] ""  DCDC
 SG_ P2D_PrgInfo_Data4 : 32|8@1+ (1,0) [0|255] ""  DCDC
 SG_ P2D_PrgInfo_Data5 : 40|8@1+ (1,0) [0|255] ""  DCDC
 SG_ P2D_PrgInfo_Data6 : 48|8@1+ (1,0) [0|255] ""  DCDC
 SG_ P2D_PrgInfo_Data7 : 56|8@1+ (1,0) [0|255] ""  DCDC

BO_ 2149154656 P2D_PrgInfo__32: 8 PC
 SG_ P2D_PrgInfo_Data0 : 0|8@1+ (1,0) [0|255] ""  DCDC
 SG_ P2D_PrgInfo_Data1 : 8|8@1+ (1,0) [0|255] ""  DCDC
 SG_ P2D_PrgInfo_Data2 : 16|8@1+ (1,0) [0|255] ""  DCDC
 SG_ P2D_PrgInfo_Data3 : 24|8@1+ (1,0) [0|255] ""  DCDC
 SG_ P2D_PrgInfo_Data4 : 32|8@1+ (1,0) [0|255] ""  DCDC
 SG_ P2D_PrgInfo_Data5 : 40|8@1+ (1,0) [0|255] ""  DCDC
 SG_ P2D_PrgInfo_Data6 : 48|8@1+ (1,0) [0|255] ""  DCDC
 SG_ P2D_PrgInfo_Data7 : 56|8@1+ (1,0) [0|255] ""  DCDC

BO_ 2149154657 P2D_PrgInfo__33: 8 PC
 SG_ P2D_PrgInfo_Data0 : 0|8@1+ (1,0) [0|255] ""  DCDC
 SG_ P2D_PrgInfo_Data1 : 8|8@1+ (1,0) [0|255] ""  DCDC
 SG_ P2D_PrgInfo_Data2 : 16|8@1+ (1,0) [0|255] ""  DCDC
 SG_ P2D_PrgInfo_Data3 : 24|8@1+ (1,0) [0|255] ""  DCDC
 SG_ P2D_PrgInfo_Data4 : 32|8@1+ (1,0) [0|255] ""  DCDC
 SG_ P2D_PrgInfo_Data5 : 40|8@1+ (1,0) [0|255] ""  DCDC
 SG_ P2D_PrgInfo_Data6 : 48|8@1+ (1,0) [0|255] ""  DCDC
 SG_ P2D_PrgInfo_Data7 : 56|8@1+ (1,0) [0|255] ""  DCDC

BO_ 2149154658 P2D_PrgInfo__34: 8 PC
 SG_ P2D_PrgInfo_Data0 : 0|8@1+ (1,0) [0|255] ""  DCDC
 SG_ P2D_PrgInfo_Data1 : 8|8@1+ (1,0) [0|255] ""  DCDC
 SG_ P2D_PrgInfo_Data2 : 16|8@1+ (1,0) [0|255] ""  DCDC
 SG_ P2D_PrgInfo_Data3 : 24|8@1+ (1,0) [0|255] ""  DCDC
 SG_ P2D_PrgInfo_Data4 : 32|8@1+ (1,0) [0|255] ""  DCDC
 SG_ P2D_PrgInfo_Data5 : 40|8@1+ (1,0) [0|255] ""  DCDC
 SG_ P2D_PrgInfo_Data6 : 48|8@1+ (1,0) [0|255] ""  DCDC
 SG_ P2D_PrgInfo_Data7 : 56|8@1+ (1,0) [0|255] ""  DCDC

BO_ 2149154659 P2D_PrgInfo__35: 8 PC
 SG_ P2D_PrgInfo_Data0 : 0|8@1+ (1,0) [0|255] ""  DCDC
 SG_ P2D_PrgInfo_Data1 : 8|8@1+ (1,0) [0|255] ""  DCDC
 SG_ P2D_PrgInfo_Data2 : 16|8@1+ (1,0) [0|255] ""  DCDC
 SG_ P2D_PrgInfo_Data3 : 24|8@1+ (1,0) [0|255] ""  DCDC
 SG_ P2D_PrgInfo_Data4 : 32|8@1+ (1,0) [0|255] ""  DCDC
 SG_ P2D_PrgInfo_Data5 : 40|8@1+ (1,0) [0|255] ""  DCDC
 SG_ P2D_PrgInfo_Data6 : 48|8@1+ (1,0) [0|255] ""  DCDC
 SG_ P2D_PrgInfo_Data7 : 56|8@1+ (1,0) [0|255] ""  DCDC

BO_ 2149154660 P2D_PrgInfo__36: 8 PC
 SG_ P2D_PrgInfo_Data0 : 0|8@1+ (1,0) [0|255] ""  DCDC
 SG_ P2D_PrgInfo_Data1 : 8|8@1+ (1,0) [0|255] ""  DCDC
 SG_ P2D_PrgInfo_Data2 : 16|8@1+ (1,0) [0|255] ""  DCDC
 SG_ P2D_PrgInfo_Data3 : 24|8@1+ (1,0) [0|255] ""  DCDC
 SG_ P2D_PrgInfo_Data4 : 32|8@1+ (1,0) [0|255] ""  DCDC
 SG_ P2D_PrgInfo_Data5 : 40|8@1+ (1,0) [0|255] ""  DCDC
 SG_ P2D_PrgInfo_Data6 : 48|8@1+ (1,0) [0|255] ""  DCDC
 SG_ P2D_PrgInfo_Data7 : 56|8@1+ (1,0) [0|255] ""  DCDC

BO_ 2149154661 P2D_PrgInfo__37: 8 PC
 SG_ P2D_PrgInfo_Data0 : 0|8@1+ (1,0) [0|255] ""  DCDC
 SG_ P2D_PrgInfo_Data1 : 8|8@1+ (1,0) [0|255] ""  DCDC
 SG_ P2D_PrgInfo_Data2 : 16|8@1+ (1,0) [0|255] ""  DCDC
 SG_ P2D_PrgInfo_Data3 : 24|8@1+ (1,0) [0|255] ""  DCDC
 SG_ P2D_PrgInfo_Data4 : 32|8@1+ (1,0) [0|255] ""  DCDC
 SG_ P2D_PrgInfo_Data5 : 40|8@1+ (1,0) [0|255] ""  DCDC
 SG_ P2D_PrgInfo_Data6 : 48|8@1+ (1,0) [0|255] ""  DCDC
 SG_ P2D_PrgInfo_Data7 : 56|8@1+ (1,0) [0|255] ""  DCDC

BO_ 2149154662 P2D_PrgInfo__38: 8 PC
 SG_ P2D_PrgInfo_Data0 : 0|8@1+ (1,0) [0|255] ""  DCDC
 SG_ P2D_PrgInfo_Data1 : 8|8@1+ (1,0) [0|255] ""  DCDC
 SG_ P2D_PrgInfo_Data2 : 16|8@1+ (1,0) [0|255] ""  DCDC
 SG_ P2D_PrgInfo_Data3 : 24|8@1+ (1,0) [0|255] ""  DCDC
 SG_ P2D_PrgInfo_Data4 : 32|8@1+ (1,0) [0|255] ""  DCDC
 SG_ P2D_PrgInfo_Data5 : 40|8@1+ (1,0) [0|255] ""  DCDC
 SG_ P2D_PrgInfo_Data6 : 48|8@1+ (1,0) [0|255] ""  DCDC
 SG_ P2D_PrgInfo_Data7 : 56|8@1+ (1,0) [0|255] ""  DCDC

BO_ 2149154663 P2D_PrgInfo__39: 8 PC
 SG_ P2D_PrgInfo_Data0 : 0|8@1+ (1,0) [0|255] ""  DCDC
 SG_ P2D_PrgInfo_Data1 : 8|8@1+ (1,0) [0|255] ""  DCDC
 SG_ P2D_PrgInfo_Data2 : 16|8@1+ (1,0) [0|255] ""  DCDC
 SG_ P2D_PrgInfo_Data3 : 24|8@1+ (1,0) [0|255] ""  DCDC
 SG_ P2D_PrgInfo_Data4 : 32|8@1+ (1,0) [0|255] ""  DCDC
 SG_ P2D_PrgInfo_Data5 : 40|8@1+ (1,0) [0|255] ""  DCDC
 SG_ P2D_PrgInfo_Data6 : 48|8@1+ (1,0) [0|255] ""  DCDC
 SG_ P2D_PrgInfo_Data7 : 56|8@1+ (1,0) [0|255] ""  DCDC

BO_ 2149154664 P2D_PrgInfo__40: 8 PC
 SG_ P2D_PrgInfo_Data0 : 0|8@1+ (1,0) [0|255] ""  DCDC
 SG_ P2D_PrgInfo_Data1 : 8|8@1+ (1,0) [0|255] ""  DCDC
 SG_ P2D_PrgInfo_Data2 : 16|8@1+ (1,0) [0|255] ""  DCDC
 SG_ P2D_PrgInfo_Data3 : 24|8@1+ (1,0) [0|255] ""  DCDC
 SG_ P2D_PrgInfo_Data4 : 32|8@1+ (1,0) [0|255] ""  DCDC
 SG_ P2D_PrgInfo_Data5 : 40|8@1+ (1,0) [0|255] ""  DCDC
 SG_ P2D_PrgInfo_Data6 : 48|8@1+ (1,0) [0|255] ""  DCDC
 SG_ P2D_PrgInfo_Data7 : 56|8@1+ (1,0) [0|255] ""  DCDC

BO_ 2149154665 P2D_PrgInfo__41: 8 PC
 SG_ P2D_PrgInfo_Data0 : 0|8@1+ (1,0) [0|255] ""  DCDC
 SG_ P2D_PrgInfo_Data1 : 8|8@1+ (1,0) [0|255] ""  DCDC
 SG_ P2D_PrgInfo_Data2 : 16|8@1+ (1,0) [0|255] ""  DCDC
 SG_ P2D_PrgInfo_Data3 : 24|8@1+ (1,0) [0|255] ""  DCDC
 SG_ P2D_PrgInfo_Data4 : 32|8@1+ (1,0) [0|255] ""  DCDC
 SG_ P2D_PrgInfo_Data5 : 40|8@1+ (1,0) [0|255] ""  DCDC
 SG_ P2D_PrgInfo_Data6 : 48|8@1+ (1,0) [0|255] ""  DCDC
 SG_ P2D_PrgInfo_Data7 : 56|8@1+ (1,0) [0|255] ""  DCDC

BO_ 2149154666 P2D_PrgInfo__42: 8 PC
 SG_ P2D_PrgInfo_Data0 : 0|8@1+ (1,0) [0|255] ""  DCDC
 SG_ P2D_PrgInfo_Data1 : 8|8@1+ (1,0) [0|255] ""  DCDC
 SG_ P2D_PrgInfo_Data2 : 16|8@1+ (1,0) [0|255] ""  DCDC
 SG_ P2D_PrgInfo_Data3 : 24|8@1+ (1,0) [0|255] ""  DCDC
 SG_ P2D_PrgInfo_Data4 : 32|8@1+ (1,0) [0|255] ""  DCDC
 SG_ P2D_PrgInfo_Data5 : 40|8@1+ (1,0) [0|255] ""  DCDC
 SG_ P2D_PrgInfo_Data6 : 48|8@1+ (1,0) [0|255] ""  DCDC
 SG_ P2D_PrgInfo_Data7 : 56|8@1+ (1,0) [0|255] ""  DCDC

BO_ 2149154667 P2D_PrgInfo__43: 8 PC
 SG_ P2D_PrgInfo_Data0 : 0|8@1+ (1,0) [0|255] ""  DCDC
 SG_ P2D_PrgInfo_Data1 : 8|8@1+ (1,0) [0|255] ""  DCDC
 SG_ P2D_PrgInfo_Data2 : 16|8@1+ (1,0) [0|255] ""  DCDC
 SG_ P2D_PrgInfo_Data3 : 24|8@1+ (1,0) [0|255] ""  DCDC
 SG_ P2D_PrgInfo_Data4 : 32|8@1+ (1,0) [0|255] ""  DCDC
 SG_ P2D_PrgInfo_Data5 : 40|8@1+ (1,0) [0|255] ""  DCDC
 SG_ P2D_PrgInfo_Data6 : 48|8@1+ (1,0) [0|255] ""  DCDC
 SG_ P2D_PrgInfo_Data7 : 56|8@1+ (1,0) [0|255] ""  DCDC

BO_ 2149154668 P2D_PrgInfo__44: 8 PC
 SG_ P2D_PrgInfo_Data0 : 0|8@1+ (1,0) [0|255] ""  DCDC
 SG_ P2D_PrgInfo_Data1 : 8|8@1+ (1,0) [0|255] ""  DCDC
 SG_ P2D_PrgInfo_Data2 : 16|8@1+ (1,0) [0|255] ""  DCDC
 SG_ P2D_PrgInfo_Data3 : 24|8@1+ (1,0) [0|255] ""  DCDC
 SG_ P2D_PrgInfo_Data4 : 32|8@1+ (1,0) [0|255] ""  DCDC
 SG_ P2D_PrgInfo_Data5 : 40|8@1+ (1,0) [0|255] ""  DCDC
 SG_ P2D_PrgInfo_Data6 : 48|8@1+ (1,0) [0|255] ""  DCDC
 SG_ P2D_PrgInfo_Data7 : 56|8@1+ (1,0) [0|255] ""  DCDC

BO_ 2149154669 P2D_PrgInfo__45: 8 PC
 SG_ P2D_PrgInfo_Data0 : 0|8@1+ (1,0) [0|255] ""  DCDC
 SG_ P2D_PrgInfo_Data1 : 8|8@1+ (1,0) [0|255] ""  DCDC
 SG_ P2D_PrgInfo_Data2 : 16|8@1+ (1,0) [0|255] ""  DCDC
 SG_ P2D_PrgInfo_Data3 : 24|8@1+ (1,0) [0|255] ""  DCDC
 SG_ P2D_PrgInfo_Data4 : 32|8@1+ (1,0) [0|255] ""  DCDC
 SG_ P2D_PrgInfo_Data5 : 40|8@1+ (1,0) [0|255] ""  DCDC
 SG_ P2D_PrgInfo_Data6 : 48|8@1+ (1,0) [0|255] ""  DCDC
 SG_ P2D_PrgInfo_Data7 : 56|8@1+ (1,0) [0|255] ""  DCDC

BO_ 2149154670 P2D_PrgInfo__46: 8 PC
 SG_ P2D_PrgInfo_Data0 : 0|8@1+ (1,0) [0|255] ""  DCDC
 SG_ P2D_PrgInfo_Data1 : 8|8@1+ (1,0) [0|255] ""  DCDC
 SG_ P2D_PrgInfo_Data2 : 16|8@1+ (1,0) [0|255] ""  DCDC
 SG_ P2D_PrgInfo_Data3 : 24|8@1+ (1,0) [0|255] ""  DCDC
 SG_ P2D_PrgInfo_Data4 : 32|8@1+ (1,0) [0|255] ""  DCDC
 SG_ P2D_PrgInfo_Data5 : 40|8@1+ (1,0) [0|255] ""  DCDC
 SG_ P2D_PrgInfo_Data6 : 48|8@1+ (1,0) [0|255] ""  DCDC
 SG_ P2D_PrgInfo_Data7 : 56|8@1+ (1,0) [0|255] ""  DCDC

BO_ 2149154671 P2D_PrgInfo__47: 8 PC
 SG_ P2D_PrgInfo_Data0 : 0|8@1+ (1,0) [0|255] ""  DCDC
 SG_ P2D_PrgInfo_Data1 : 8|8@1+ (1,0) [0|255] ""  DCDC
 SG_ P2D_PrgInfo_Data2 : 16|8@1+ (1,0) [0|255] ""  DCDC
 SG_ P2D_PrgInfo_Data3 : 24|8@1+ (1,0) [0|255] ""  DCDC
 SG_ P2D_PrgInfo_Data4 : 32|8@1+ (1,0) [0|255] ""  DCDC
 SG_ P2D_PrgInfo_Data5 : 40|8@1+ (1,0) [0|255] ""  DCDC
 SG_ P2D_PrgInfo_Data6 : 48|8@1+ (1,0) [0|255] ""  DCDC
 SG_ P2D_PrgInfo_Data7 : 56|8@1+ (1,0) [0|255] ""  DCDC

BO_ 2149154672 P2D_PrgInfo__48: 8 PC
 SG_ P2D_PrgInfo_Data0 : 0|8@1+ (1,0) [0|255] ""  DCDC
 SG_ P2D_PrgInfo_Data1 : 8|8@1+ (1,0) [0|255] ""  DCDC
 SG_ P2D_PrgInfo_Data2 : 16|8@1+ (1,0) [0|255] ""  DCDC
 SG_ P2D_PrgInfo_Data3 : 24|8@1+ (1,0) [0|255] ""  DCDC
 SG_ P2D_PrgInfo_Data4 : 32|8@1+ (1,0) [0|255] ""  DCDC
 SG_ P2D_PrgInfo_Data5 : 40|8@1+ (1,0) [0|255] ""  DCDC
 SG_ P2D_PrgInfo_Data6 : 48|8@1+ (1,0) [0|255] ""  DCDC
 SG_ P2D_PrgInfo_Data7 : 56|8@1+ (1,0) [0|255] ""  DCDC

BO_ 2149154673 P2D_PrgInfo__49: 8 PC
 SG_ P2D_PrgInfo_Data0 : 0|8@1+ (1,0) [0|255] ""  DCDC
 SG_ P2D_PrgInfo_Data1 : 8|8@1+ (1,0) [0|255] ""  DCDC
 SG_ P2D_PrgInfo_Data2 : 16|8@1+ (1,0) [0|255] ""  DCDC
 SG_ P2D_PrgInfo_Data3 : 24|8@1+ (1,0) [0|255] ""  DCDC
 SG_ P2D_PrgInfo_Data4 : 32|8@1+ (1,0) [0|255] ""  DCDC
 SG_ P2D_PrgInfo_Data5 : 40|8@1+ (1,0) [0|255] ""  DCDC
 SG_ P2D_PrgInfo_Data6 : 48|8@1+ (1,0) [0|255] ""  DCDC
 SG_ P2D_PrgInfo_Data7 : 56|8@1+ (1,0) [0|255] ""  DCDC

BO_ 2149154674 P2D_PrgInfo__50: 8 PC
 SG_ P2D_PrgInfo_Data0 : 0|8@1+ (1,0) [0|255] ""  DCDC
 SG_ P2D_PrgInfo_Data1 : 8|8@1+ (1,0) [0|255] ""  DCDC
 SG_ P2D_PrgInfo_Data2 : 16|8@1+ (1,0) [0|255] ""  DCDC
 SG_ P2D_PrgInfo_Data3 : 24|8@1+ (1,0) [0|255] ""  DCDC
 SG_ P2D_PrgInfo_Data4 : 32|8@1+ (1,0) [0|255] ""  DCDC
 SG_ P2D_PrgInfo_Data5 : 40|8@1+ (1,0) [0|255] ""  DCDC
 SG_ P2D_PrgInfo_Data6 : 48|8@1+ (1,0) [0|255] ""  DCDC
 SG_ P2D_PrgInfo_Data7 : 56|8@1+ (1,0) [0|255] ""  DCDC

BO_ 2149154675 P2D_PrgInfo__51: 8 PC
 SG_ P2D_PrgInfo_Data0 : 0|8@1+ (1,0) [0|255] ""  DCDC
 SG_ P2D_PrgInfo_Data1 : 8|8@1+ (1,0) [0|255] ""  DCDC
 SG_ P2D_PrgInfo_Data2 : 16|8@1+ (1,0) [0|255] ""  DCDC
 SG_ P2D_PrgInfo_Data3 : 24|8@1+ (1,0) [0|255] ""  DCDC
 SG_ P2D_PrgInfo_Data4 : 32|8@1+ (1,0) [0|255] ""  DCDC
 SG_ P2D_PrgInfo_Data5 : 40|8@1+ (1,0) [0|255] ""  DCDC
 SG_ P2D_PrgInfo_Data6 : 48|8@1+ (1,0) [0|255] ""  DCDC
 SG_ P2D_PrgInfo_Data7 : 56|8@1+ (1,0) [0|255] ""  DCDC

BO_ 2149154676 P2D_PrgInfo__52: 8 PC
 SG_ P2D_PrgInfo_Data0 : 0|8@1+ (1,0) [0|255] ""  DCDC
 SG_ P2D_PrgInfo_Data1 : 8|8@1+ (1,0) [0|255] ""  DCDC
 SG_ P2D_PrgInfo_Data2 : 16|8@1+ (1,0) [0|255] ""  DCDC
 SG_ P2D_PrgInfo_Data3 : 24|8@1+ (1,0) [0|255] ""  DCDC
 SG_ P2D_PrgInfo_Data4 : 32|8@1+ (1,0) [0|255] ""  DCDC
 SG_ P2D_PrgInfo_Data5 : 40|8@1+ (1,0) [0|255] ""  DCDC
 SG_ P2D_PrgInfo_Data6 : 48|8@1+ (1,0) [0|255] ""  DCDC
 SG_ P2D_PrgInfo_Data7 : 56|8@1+ (1,0) [0|255] ""  DCDC

BO_ 2149154677 P2D_PrgInfo__53: 8 PC
 SG_ P2D_PrgInfo_Data0 : 0|8@1+ (1,0) [0|255] ""  DCDC
 SG_ P2D_PrgInfo_Data1 : 8|8@1+ (1,0) [0|255] ""  DCDC
 SG_ P2D_PrgInfo_Data2 : 16|8@1+ (1,0) [0|255] ""  DCDC
 SG_ P2D_PrgInfo_Data3 : 24|8@1+ (1,0) [0|255] ""  DCDC
 SG_ P2D_PrgInfo_Data4 : 32|8@1+ (1,0) [0|255] ""  DCDC
 SG_ P2D_PrgInfo_Data5 : 40|8@1+ (1,0) [0|255] ""  DCDC
 SG_ P2D_PrgInfo_Data6 : 48|8@1+ (1,0) [0|255] ""  DCDC
 SG_ P2D_PrgInfo_Data7 : 56|8@1+ (1,0) [0|255] ""  DCDC

BO_ 2149154678 P2D_PrgInfo__54: 8 PC
 SG_ P2D_PrgInfo_Data0 : 0|8@1+ (1,0) [0|255] ""  DCDC
 SG_ P2D_PrgInfo_Data1 : 8|8@1+ (1,0) [0|255] ""  DCDC
 SG_ P2D_PrgInfo_Data2 : 16|8@1+ (1,0) [0|255] ""  DCDC
 SG_ P2D_PrgInfo_Data3 : 24|8@1+ (1,0) [0|255] ""  DCDC
 SG_ P2D_PrgInfo_Data4 : 32|8@1+ (1,0) [0|255] ""  DCDC
 SG_ P2D_PrgInfo_Data5 : 40|8@1+ (1,0) [0|255] ""  DCDC
 SG_ P2D_PrgInfo_Data6 : 48|8@1+ (1,0) [0|255] ""  DCDC
 SG_ P2D_PrgInfo_Data7 : 56|8@1+ (1,0) [0|255] ""  DCDC

BO_ 2149154679 P2D_PrgInfo__55: 8 PC
 SG_ P2D_PrgInfo_Data0 : 0|8@1+ (1,0) [0|255] ""  DCDC
 SG_ P2D_PrgInfo_Data1 : 8|8@1+ (1,0) [0|255] ""  DCDC
 SG_ P2D_PrgInfo_Data2 : 16|8@1+ (1,0) [0|255] ""  DCDC
 SG_ P2D_PrgInfo_Data3 : 24|8@1+ (1,0) [0|255] ""  DCDC
 SG_ P2D_PrgInfo_Data4 : 32|8@1+ (1,0) [0|255] ""  DCDC
 SG_ P2D_PrgInfo_Data5 : 40|8@1+ (1,0) [0|255] ""  DCDC
 SG_ P2D_PrgInfo_Data6 : 48|8@1+ (1,0) [0|255] ""  DCDC
 SG_ P2D_PrgInfo_Data7 : 56|8@1+ (1,0) [0|255] ""  DCDC

BO_ 2149154680 P2D_PrgInfo__56: 8 PC
 SG_ P2D_PrgInfo_Data0 : 0|8@1+ (1,0) [0|255] ""  DCDC
 SG_ P2D_PrgInfo_Data1 : 8|8@1+ (1,0) [0|255] ""  DCDC
 SG_ P2D_PrgInfo_Data2 : 16|8@1+ (1,0) [0|255] ""  DCDC
 SG_ P2D_PrgInfo_Data3 : 24|8@1+ (1,0) [0|255] ""  DCDC
 SG_ P2D_PrgInfo_Data4 : 32|8@1+ (1,0) [0|255] ""  DCDC
 SG_ P2D_PrgInfo_Data5 : 40|8@1+ (1,0) [0|255] ""  DCDC
 SG_ P2D_PrgInfo_Data6 : 48|8@1+ (1,0) [0|255] ""  DCDC
 SG_ P2D_PrgInfo_Data7 : 56|8@1+ (1,0) [0|255] ""  DCDC

BO_ 2149154681 P2D_PrgInfo__57: 8 PC
 SG_ P2D_PrgInfo_Data0 : 0|8@1+ (1,0) [0|255] ""  DCDC
 SG_ P2D_PrgInfo_Data1 : 8|8@1+ (1,0) [0|255] ""  DCDC
 SG_ P2D_PrgInfo_Data2 : 16|8@1+ (1,0) [0|255] ""  DCDC
 SG_ P2D_PrgInfo_Data3 : 24|8@1+ (1,0) [0|255] ""  DCDC
 SG_ P2D_PrgInfo_Data4 : 32|8@1+ (1,0) [0|255] ""  DCDC
 SG_ P2D_PrgInfo_Data5 : 40|8@1+ (1,0) [0|255] ""  DCDC
 SG_ P2D_PrgInfo_Data6 : 48|8@1+ (1,0) [0|255] ""  DCDC
 SG_ P2D_PrgInfo_Data7 : 56|8@1+ (1,0) [0|255] ""  DCDC

BO_ 2149154682 P2D_PrgInfo__58: 8 PC
 SG_ P2D_PrgInfo_Data0 : 0|8@1+ (1,0) [0|255] ""  DCDC
 SG_ P2D_PrgInfo_Data1 : 8|8@1+ (1,0) [0|255] ""  DCDC
 SG_ P2D_PrgInfo_Data2 : 16|8@1+ (1,0) [0|255] ""  DCDC
 SG_ P2D_PrgInfo_Data3 : 24|8@1+ (1,0) [0|255] ""  DCDC
 SG_ P2D_PrgInfo_Data4 : 32|8@1+ (1,0) [0|255] ""  DCDC
 SG_ P2D_PrgInfo_Data5 : 40|8@1+ (1,0) [0|255] ""  DCDC
 SG_ P2D_PrgInfo_Data6 : 48|8@1+ (1,0) [0|255] ""  DCDC
 SG_ P2D_PrgInfo_Data7 : 56|8@1+ (1,0) [0|255] ""  DCDC

BO_ 2149154683 P2D_PrgInfo__59: 8 PC
 SG_ P2D_PrgInfo_Data0 : 0|8@1+ (1,0) [0|255] ""  DCDC
 SG_ P2D_PrgInfo_Data1 : 8|8@1+ (1,0) [0|255] ""  DCDC
 SG_ P2D_PrgInfo_Data2 : 16|8@1+ (1,0) [0|255] ""  DCDC
 SG_ P2D_PrgInfo_Data3 : 24|8@1+ (1,0) [0|255] ""  DCDC
 SG_ P2D_PrgInfo_Data4 : 32|8@1+ (1,0) [0|255] ""  DCDC
 SG_ P2D_PrgInfo_Data5 : 40|8@1+ (1,0) [0|255] ""  DCDC
 SG_ P2D_PrgInfo_Data6 : 48|8@1+ (1,0) [0|255] ""  DCDC
 SG_ P2D_PrgInfo_Data7 : 56|8@1+ (1,0) [0|255] ""  DCDC

BO_ 2149154684 P2D_PrgInfo__60: 8 PC
 SG_ P2D_PrgInfo_Data0 : 0|8@1+ (1,0) [0|255] ""  DCDC
 SG_ P2D_PrgInfo_Data1 : 8|8@1+ (1,0) [0|255] ""  DCDC
 SG_ P2D_PrgInfo_Data2 : 16|8@1+ (1,0) [0|255] ""  DCDC
 SG_ P2D_PrgInfo_Data3 : 24|8@1+ (1,0) [0|255] ""  DCDC
 SG_ P2D_PrgInfo_Data4 : 32|8@1+ (1,0) [0|255] ""  DCDC
 SG_ P2D_PrgInfo_Data5 : 40|8@1+ (1,0) [0|255] ""  DCDC
 SG_ P2D_PrgInfo_Data6 : 48|8@1+ (1,0) [0|255] ""  DCDC
 SG_ P2D_PrgInfo_Data7 : 56|8@1+ (1,0) [0|255] ""  DCDC

BO_ 2149154685 P2D_PrgInfo__61: 8 PC
 SG_ P2D_PrgInfo_Data0 : 0|8@1+ (1,0) [0|255] ""  DCDC
 SG_ P2D_PrgInfo_Data1 : 8|8@1+ (1,0) [0|255] ""  DCDC
 SG_ P2D_PrgInfo_Data2 : 16|8@1+ (1,0) [0|255] ""  DCDC
 SG_ P2D_PrgInfo_Data3 : 24|8@1+ (1,0) [0|255] ""  DCDC
 SG_ P2D_PrgInfo_Data4 : 32|8@1+ (1,0) [0|255] ""  DCDC
 SG_ P2D_PrgInfo_Data5 : 40|8@1+ (1,0) [0|255] ""  DCDC
 SG_ P2D_PrgInfo_Data6 : 48|8@1+ (1,0) [0|255] ""  DCDC
 SG_ P2D_PrgInfo_Data7 : 56|8@1+ (1,0) [0|255] ""  DCDC

BO_ 2149154686 P2D_PrgInfo__62: 8 PC
 SG_ P2D_PrgInfo_Data0 : 0|8@1+ (1,0) [0|255] ""  DCDC
 SG_ P2D_PrgInfo_Data1 : 8|8@1+ (1,0) [0|255] ""  DCDC
 SG_ P2D_PrgInfo_Data2 : 16|8@1+ (1,0) [0|255] ""  DCDC
 SG_ P2D_PrgInfo_Data3 : 24|8@1+ (1,0) [0|255] ""  DCDC
 SG_ P2D_PrgInfo_Data4 : 32|8@1+ (1,0) [0|255] ""  DCDC
 SG_ P2D_PrgInfo_Data5 : 40|8@1+ (1,0) [0|255] ""  DCDC
 SG_ P2D_PrgInfo_Data6 : 48|8@1+ (1,0) [0|255] ""  DCDC
 SG_ P2D_PrgInfo_Data7 : 56|8@1+ (1,0) [0|255] ""  DCDC

BO_ 2149154687 P2D_PrgInfo__63: 8 PC
 SG_ P2D_PrgInfo_Data0 : 0|8@1+ (1,0) [0|255] ""  DCDC
 SG_ P2D_PrgInfo_Data1 : 8|8@1+ (1,0) [0|255] ""  DCDC
 SG_ P2D_PrgInfo_Data2 : 16|8@1+ (1,0) [0|255] ""  DCDC
 SG_ P2D_PrgInfo_Data3 : 24|8@1+ (1,0) [0|255] ""  DCDC
 SG_ P2D_PrgInfo_Data4 : 32|8@1+ (1,0) [0|255] ""  DCDC
 SG_ P2D_PrgInfo_Data5 : 40|8@1+ (1,0) [0|255] ""  DCDC
 SG_ P2D_PrgInfo_Data6 : 48|8@1+ (1,0) [0|255] ""  DCDC
 SG_ P2D_PrgInfo_Data7 : 56|8@1+ (1,0) [0|255] ""  DCDC

BO_ 2149220161 P2D_DLoadInfo__01: 8 PC
 SG_ P2D_DLoadInfo_Data0 : 0|8@1+ (1,0) [0|255] ""  DCDC
 SG_ P2D_DLoadInfo_Data1 : 8|8@1+ (1,0) [0|255] ""  DCDC
 SG_ P2D_DLoadInfo_Data2 : 16|8@1+ (1,0) [0|255] ""  DCDC
 SG_ P2D_DLoadInfo_Data3 : 24|8@1+ (1,0) [0|255] ""  DCDC
 SG_ P2D_DLoadInfo_Data4 : 32|8@1+ (1,0) [0|255] ""  DCDC
 SG_ P2D_DLoadInfo_Data5 : 40|8@1+ (1,0) [0|255] ""  DCDC
 SG_ P2D_DLoadInfo_Data6 : 48|8@1+ (1,0) [0|255] ""  DCDC
 SG_ P2D_DLoadInfo_Data7 : 56|8@1+ (1,0) [0|255] ""  DCDC

BO_ 2149220162 P2D_DLoadInfo__02: 8 PC
 SG_ P2D_DLoadInfo_Data0 : 0|8@1+ (1,0) [0|255] ""  DCDC
 SG_ P2D_DLoadInfo_Data1 : 8|8@1+ (1,0) [0|255] ""  DCDC
 SG_ P2D_DLoadInfo_Data2 : 16|8@1+ (1,0) [0|255] ""  DCDC
 SG_ P2D_DLoadInfo_Data3 : 24|8@1+ (1,0) [0|255] ""  DCDC
 SG_ P2D_DLoadInfo_Data4 : 32|8@1+ (1,0) [0|255] ""  DCDC
 SG_ P2D_DLoadInfo_Data5 : 40|8@1+ (1,0) [0|255] ""  DCDC
 SG_ P2D_DLoadInfo_Data6 : 48|8@1+ (1,0) [0|255] ""  DCDC
 SG_ P2D_DLoadInfo_Data7 : 56|8@1+ (1,0) [0|255] ""  DCDC

BO_ 2149220163 P2D_DLoadInfo__03: 8 PC
 SG_ P2D_DLoadInfo_Data0 : 0|8@1+ (1,0) [0|255] ""  DCDC
 SG_ P2D_DLoadInfo_Data1 : 8|8@1+ (1,0) [0|255] ""  DCDC
 SG_ P2D_DLoadInfo_Data2 : 16|8@1+ (1,0) [0|255] ""  DCDC
 SG_ P2D_DLoadInfo_Data3 : 24|8@1+ (1,0) [0|255] ""  DCDC
 SG_ P2D_DLoadInfo_Data4 : 32|8@1+ (1,0) [0|255] ""  DCDC
 SG_ P2D_DLoadInfo_Data5 : 40|8@1+ (1,0) [0|255] ""  DCDC
 SG_ P2D_DLoadInfo_Data6 : 48|8@1+ (1,0) [0|255] ""  DCDC
 SG_ P2D_DLoadInfo_Data7 : 56|8@1+ (1,0) [0|255] ""  DCDC

BO_ 2149220164 P2D_DLoadInfo__04: 8 PC
 SG_ P2D_DLoadInfo_Data0 : 0|8@1+ (1,0) [0|255] ""  DCDC
 SG_ P2D_DLoadInfo_Data1 : 8|8@1+ (1,0) [0|255] ""  DCDC
 SG_ P2D_DLoadInfo_Data2 : 16|8@1+ (1,0) [0|255] ""  DCDC
 SG_ P2D_DLoadInfo_Data3 : 24|8@1+ (1,0) [0|255] ""  DCDC
 SG_ P2D_DLoadInfo_Data4 : 32|8@1+ (1,0) [0|255] ""  DCDC
 SG_ P2D_DLoadInfo_Data5 : 40|8@1+ (1,0) [0|255] ""  DCDC
 SG_ P2D_DLoadInfo_Data6 : 48|8@1+ (1,0) [0|255] ""  DCDC
 SG_ P2D_DLoadInfo_Data7 : 56|8@1+ (1,0) [0|255] ""  DCDC

BO_ 2149220165 P2D_DLoadInfo__05: 8 PC
 SG_ P2D_DLoadInfo_Data0 : 0|8@1+ (1,0) [0|255] ""  DCDC
 SG_ P2D_DLoadInfo_Data1 : 8|8@1+ (1,0) [0|255] ""  DCDC
 SG_ P2D_DLoadInfo_Data2 : 16|8@1+ (1,0) [0|255] ""  DCDC
 SG_ P2D_DLoadInfo_Data3 : 24|8@1+ (1,0) [0|255] ""  DCDC
 SG_ P2D_DLoadInfo_Data4 : 32|8@1+ (1,0) [0|255] ""  DCDC
 SG_ P2D_DLoadInfo_Data5 : 40|8@1+ (1,0) [0|255] ""  DCDC
 SG_ P2D_DLoadInfo_Data6 : 48|8@1+ (1,0) [0|255] ""  DCDC
 SG_ P2D_DLoadInfo_Data7 : 56|8@1+ (1,0) [0|255] ""  DCDC

BO_ 2149220166 P2D_DLoadInfo__06: 8 PC
 SG_ P2D_DLoadInfo_Data0 : 0|8@1+ (1,0) [0|255] ""  DCDC
 SG_ P2D_DLoadInfo_Data1 : 8|8@1+ (1,0) [0|255] ""  DCDC
 SG_ P2D_DLoadInfo_Data2 : 16|8@1+ (1,0) [0|255] ""  DCDC
 SG_ P2D_DLoadInfo_Data3 : 24|8@1+ (1,0) [0|255] ""  DCDC
 SG_ P2D_DLoadInfo_Data4 : 32|8@1+ (1,0) [0|255] ""  DCDC
 SG_ P2D_DLoadInfo_Data5 : 40|8@1+ (1,0) [0|255] ""  DCDC
 SG_ P2D_DLoadInfo_Data6 : 48|8@1+ (1,0) [0|255] ""  DCDC
 SG_ P2D_DLoadInfo_Data7 : 56|8@1+ (1,0) [0|255] ""  DCDC

BO_ 2149220167 P2D_DLoadInfo__07: 8 PC
 SG_ P2D_DLoadInfo_Data0 : 0|8@1+ (1,0) [0|255] ""  DCDC
 SG_ P2D_DLoadInfo_Data1 : 8|8@1+ (1,0) [0|255] ""  DCDC
 SG_ P2D_DLoadInfo_Data2 : 16|8@1+ (1,0) [0|255] ""  DCDC
 SG_ P2D_DLoadInfo_Data3 : 24|8@1+ (1,0) [0|255] ""  DCDC
 SG_ P2D_DLoadInfo_Data4 : 32|8@1+ (1,0) [0|255] ""  DCDC
 SG_ P2D_DLoadInfo_Data5 : 40|8@1+ (1,0) [0|255] ""  DCDC
 SG_ P2D_DLoadInfo_Data6 : 48|8@1+ (1,0) [0|255] ""  DCDC
 SG_ P2D_DLoadInfo_Data7 : 56|8@1+ (1,0) [0|255] ""  DCDC

BO_ 2149220168 P2D_DLoadInfo__08: 8 PC
 SG_ P2D_DLoadInfo_Data0 : 0|8@1+ (1,0) [0|255] ""  DCDC
 SG_ P2D_DLoadInfo_Data1 : 8|8@1+ (1,0) [0|255] ""  DCDC
 SG_ P2D_DLoadInfo_Data2 : 16|8@1+ (1,0) [0|255] ""  DCDC
 SG_ P2D_DLoadInfo_Data3 : 24|8@1+ (1,0) [0|255] ""  DCDC
 SG_ P2D_DLoadInfo_Data4 : 32|8@1+ (1,0) [0|255] ""  DCDC
 SG_ P2D_DLoadInfo_Data5 : 40|8@1+ (1,0) [0|255] ""  DCDC
 SG_ P2D_DLoadInfo_Data6 : 48|8@1+ (1,0) [0|255] ""  DCDC
 SG_ P2D_DLoadInfo_Data7 : 56|8@1+ (1,0) [0|255] ""  DCDC

BO_ 2149220169 P2D_DLoadInfo__09: 8 PC
 SG_ P2D_DLoadInfo_Data0 : 0|8@1+ (1,0) [0|255] ""  DCDC
 SG_ P2D_DLoadInfo_Data1 : 8|8@1+ (1,0) [0|255] ""  DCDC
 SG_ P2D_DLoadInfo_Data2 : 16|8@1+ (1,0) [0|255] ""  DCDC
 SG_ P2D_DLoadInfo_Data3 : 24|8@1+ (1,0) [0|255] ""  DCDC
 SG_ P2D_DLoadInfo_Data4 : 32|8@1+ (1,0) [0|255] ""  DCDC
 SG_ P2D_DLoadInfo_Data5 : 40|8@1+ (1,0) [0|255] ""  DCDC
 SG_ P2D_DLoadInfo_Data6 : 48|8@1+ (1,0) [0|255] ""  DCDC
 SG_ P2D_DLoadInfo_Data7 : 56|8@1+ (1,0) [0|255] ""  DCDC

BO_ 2149220170 P2D_DLoadInfo__10: 8 PC
 SG_ P2D_DLoadInfo_Data0 : 0|8@1+ (1,0) [0|255] ""  DCDC
 SG_ P2D_DLoadInfo_Data1 : 8|8@1+ (1,0) [0|255] ""  DCDC
 SG_ P2D_DLoadInfo_Data2 : 16|8@1+ (1,0) [0|255] ""  DCDC
 SG_ P2D_DLoadInfo_Data3 : 24|8@1+ (1,0) [0|255] ""  DCDC
 SG_ P2D_DLoadInfo_Data4 : 32|8@1+ (1,0) [0|255] ""  DCDC
 SG_ P2D_DLoadInfo_Data5 : 40|8@1+ (1,0) [0|255] ""  DCDC
 SG_ P2D_DLoadInfo_Data6 : 48|8@1+ (1,0) [0|255] ""  DCDC
 SG_ P2D_DLoadInfo_Data7 : 56|8@1+ (1,0) [0|255] ""  DCDC

BO_ 2149220171 P2D_DLoadInfo__11: 8 PC
 SG_ P2D_DLoadInfo_Data0 : 0|8@1+ (1,0) [0|255] ""  DCDC
 SG_ P2D_DLoadInfo_Data1 : 8|8@1+ (1,0) [0|255] ""  DCDC
 SG_ P2D_DLoadInfo_Data2 : 16|8@1+ (1,0) [0|255] ""  DCDC
 SG_ P2D_DLoadInfo_Data3 : 24|8@1+ (1,0) [0|255] ""  DCDC
 SG_ P2D_DLoadInfo_Data4 : 32|8@1+ (1,0) [0|255] ""  DCDC
 SG_ P2D_DLoadInfo_Data5 : 40|8@1+ (1,0) [0|255] ""  DCDC
 SG_ P2D_DLoadInfo_Data6 : 48|8@1+ (1,0) [0|255] ""  DCDC
 SG_ P2D_DLoadInfo_Data7 : 56|8@1+ (1,0) [0|255] ""  DCDC

BO_ 2149220172 P2D_DLoadInfo__12: 8 PC
 SG_ P2D_DLoadInfo_Data0 : 0|8@1+ (1,0) [0|255] ""  DCDC
 SG_ P2D_DLoadInfo_Data1 : 8|8@1+ (1,0) [0|255] ""  DCDC
 SG_ P2D_DLoadInfo_Data2 : 16|8@1+ (1,0) [0|255] ""  DCDC
 SG_ P2D_DLoadInfo_Data3 : 24|8@1+ (1,0) [0|255] ""  DCDC
 SG_ P2D_DLoadInfo_Data4 : 32|8@1+ (1,0) [0|255] ""  DCDC
 SG_ P2D_DLoadInfo_Data5 : 40|8@1+ (1,0) [0|255] ""  DCDC
 SG_ P2D_DLoadInfo_Data6 : 48|8@1+ (1,0) [0|255] ""  DCDC
 SG_ P2D_DLoadInfo_Data7 : 56|8@1+ (1,0) [0|255] ""  DCDC

BO_ 2149220173 P2D_DLoadInfo__13: 8 PC
 SG_ P2D_DLoadInfo_Data0 : 0|8@1+ (1,0) [0|255] ""  DCDC
 SG_ P2D_DLoadInfo_Data1 : 8|8@1+ (1,0) [0|255] ""  DCDC
 SG_ P2D_DLoadInfo_Data2 : 16|8@1+ (1,0) [0|255] ""  DCDC
 SG_ P2D_DLoadInfo_Data3 : 24|8@1+ (1,0) [0|255] ""  DCDC
 SG_ P2D_DLoadInfo_Data4 : 32|8@1+ (1,0) [0|255] ""  DCDC
 SG_ P2D_DLoadInfo_Data5 : 40|8@1+ (1,0) [0|255] ""  DCDC
 SG_ P2D_DLoadInfo_Data6 : 48|8@1+ (1,0) [0|255] ""  DCDC
 SG_ P2D_DLoadInfo_Data7 : 56|8@1+ (1,0) [0|255] ""  DCDC

BO_ 2149220174 P2D_DLoadInfo__14: 8 PC
 SG_ P2D_DLoadInfo_Data0 : 0|8@1+ (1,0) [0|255] ""  DCDC
 SG_ P2D_DLoadInfo_Data1 : 8|8@1+ (1,0) [0|255] ""  DCDC
 SG_ P2D_DLoadInfo_Data2 : 16|8@1+ (1,0) [0|255] ""  DCDC
 SG_ P2D_DLoadInfo_Data3 : 24|8@1+ (1,0) [0|255] ""  DCDC
 SG_ P2D_DLoadInfo_Data4 : 32|8@1+ (1,0) [0|255] ""  DCDC
 SG_ P2D_DLoadInfo_Data5 : 40|8@1+ (1,0) [0|255] ""  DCDC
 SG_ P2D_DLoadInfo_Data6 : 48|8@1+ (1,0) [0|255] ""  DCDC
 SG_ P2D_DLoadInfo_Data7 : 56|8@1+ (1,0) [0|255] ""  DCDC

BO_ 2149220175 P2D_DLoadInfo__15: 8 PC
 SG_ P2D_DLoadInfo_Data0 : 0|8@1+ (1,0) [0|255] ""  DCDC
 SG_ P2D_DLoadInfo_Data1 : 8|8@1+ (1,0) [0|255] ""  DCDC
 SG_ P2D_DLoadInfo_Data2 : 16|8@1+ (1,0) [0|255] ""  DCDC
 SG_ P2D_DLoadInfo_Data3 : 24|8@1+ (1,0) [0|255] ""  DCDC
 SG_ P2D_DLoadInfo_Data4 : 32|8@1+ (1,0) [0|255] ""  DCDC
 SG_ P2D_DLoadInfo_Data5 : 40|8@1+ (1,0) [0|255] ""  DCDC
 SG_ P2D_DLoadInfo_Data6 : 48|8@1+ (1,0) [0|255] ""  DCDC
 SG_ P2D_DLoadInfo_Data7 : 56|8@1+ (1,0) [0|255] ""  DCDC

BO_ 2149220176 P2D_DLoadInfo__16: 8 PC
 SG_ P2D_DLoadInfo_Data0 : 0|8@1+ (1,0) [0|255] ""  DCDC
 SG_ P2D_DLoadInfo_Data1 : 8|8@1+ (1,0) [0|255] ""  DCDC
 SG_ P2D_DLoadInfo_Data2 : 16|8@1+ (1,0) [0|255] ""  DCDC
 SG_ P2D_DLoadInfo_Data3 : 24|8@1+ (1,0) [0|255] ""  DCDC
 SG_ P2D_DLoadInfo_Data4 : 32|8@1+ (1,0) [0|255] ""  DCDC
 SG_ P2D_DLoadInfo_Data5 : 40|8@1+ (1,0) [0|255] ""  DCDC
 SG_ P2D_DLoadInfo_Data6 : 48|8@1+ (1,0) [0|255] ""  DCDC
 SG_ P2D_DLoadInfo_Data7 : 56|8@1+ (1,0) [0|255] ""  DCDC

BO_ 2149220177 P2D_DLoadInfo__17: 8 PC
 SG_ P2D_DLoadInfo_Data0 : 0|8@1+ (1,0) [0|255] ""  DCDC
 SG_ P2D_DLoadInfo_Data1 : 8|8@1+ (1,0) [0|255] ""  DCDC
 SG_ P2D_DLoadInfo_Data2 : 16|8@1+ (1,0) [0|255] ""  DCDC
 SG_ P2D_DLoadInfo_Data3 : 24|8@1+ (1,0) [0|255] ""  DCDC
 SG_ P2D_DLoadInfo_Data4 : 32|8@1+ (1,0) [0|255] ""  DCDC
 SG_ P2D_DLoadInfo_Data5 : 40|8@1+ (1,0) [0|255] ""  DCDC
 SG_ P2D_DLoadInfo_Data6 : 48|8@1+ (1,0) [0|255] ""  DCDC
 SG_ P2D_DLoadInfo_Data7 : 56|8@1+ (1,0) [0|255] ""  DCDC

BO_ 2149220178 P2D_DLoadInfo__18: 8 PC
 SG_ P2D_DLoadInfo_Data0 : 0|8@1+ (1,0) [0|255] ""  DCDC
 SG_ P2D_DLoadInfo_Data1 : 8|8@1+ (1,0) [0|255] ""  DCDC
 SG_ P2D_DLoadInfo_Data2 : 16|8@1+ (1,0) [0|255] ""  DCDC
 SG_ P2D_DLoadInfo_Data3 : 24|8@1+ (1,0) [0|255] ""  DCDC
 SG_ P2D_DLoadInfo_Data4 : 32|8@1+ (1,0) [0|255] ""  DCDC
 SG_ P2D_DLoadInfo_Data5 : 40|8@1+ (1,0) [0|255] ""  DCDC
 SG_ P2D_DLoadInfo_Data6 : 48|8@1+ (1,0) [0|255] ""  DCDC
 SG_ P2D_DLoadInfo_Data7 : 56|8@1+ (1,0) [0|255] ""  DCDC

BO_ 2149220179 P2D_DLoadInfo__19: 8 PC
 SG_ P2D_DLoadInfo_Data0 : 0|8@1+ (1,0) [0|255] ""  DCDC
 SG_ P2D_DLoadInfo_Data1 : 8|8@1+ (1,0) [0|255] ""  DCDC
 SG_ P2D_DLoadInfo_Data2 : 16|8@1+ (1,0) [0|255] ""  DCDC
 SG_ P2D_DLoadInfo_Data3 : 24|8@1+ (1,0) [0|255] ""  DCDC
 SG_ P2D_DLoadInfo_Data4 : 32|8@1+ (1,0) [0|255] ""  DCDC
 SG_ P2D_DLoadInfo_Data5 : 40|8@1+ (1,0) [0|255] ""  DCDC
 SG_ P2D_DLoadInfo_Data6 : 48|8@1+ (1,0) [0|255] ""  DCDC
 SG_ P2D_DLoadInfo_Data7 : 56|8@1+ (1,0) [0|255] ""  DCDC

BO_ 2149220180 P2D_DLoadInfo__20: 8 PC
 SG_ P2D_DLoadInfo_Data0 : 0|8@1+ (1,0) [0|255] ""  DCDC
 SG_ P2D_DLoadInfo_Data1 : 8|8@1+ (1,0) [0|255] ""  DCDC
 SG_ P2D_DLoadInfo_Data2 : 16|8@1+ (1,0) [0|255] ""  DCDC
 SG_ P2D_DLoadInfo_Data3 : 24|8@1+ (1,0) [0|255] ""  DCDC
 SG_ P2D_DLoadInfo_Data4 : 32|8@1+ (1,0) [0|255] ""  DCDC
 SG_ P2D_DLoadInfo_Data5 : 40|8@1+ (1,0) [0|255] ""  DCDC
 SG_ P2D_DLoadInfo_Data6 : 48|8@1+ (1,0) [0|255] ""  DCDC
 SG_ P2D_DLoadInfo_Data7 : 56|8@1+ (1,0) [0|255] ""  DCDC

BO_ 2149220181 P2D_DLoadInfo__21: 8 PC
 SG_ P2D_DLoadInfo_Data0 : 0|8@1+ (1,0) [0|255] ""  DCDC
 SG_ P2D_DLoadInfo_Data1 : 8|8@1+ (1,0) [0|255] ""  DCDC
 SG_ P2D_DLoadInfo_Data2 : 16|8@1+ (1,0) [0|255] ""  DCDC
 SG_ P2D_DLoadInfo_Data3 : 24|8@1+ (1,0) [0|255] ""  DCDC
 SG_ P2D_DLoadInfo_Data4 : 32|8@1+ (1,0) [0|255] ""  DCDC
 SG_ P2D_DLoadInfo_Data5 : 40|8@1+ (1,0) [0|255] ""  DCDC
 SG_ P2D_DLoadInfo_Data6 : 48|8@1+ (1,0) [0|255] ""  DCDC
 SG_ P2D_DLoadInfo_Data7 : 56|8@1+ (1,0) [0|255] ""  DCDC

BO_ 2149220182 P2D_DLoadInfo__22: 8 PC
 SG_ P2D_DLoadInfo_Data0 : 0|8@1+ (1,0) [0|255] ""  DCDC
 SG_ P2D_DLoadInfo_Data1 : 8|8@1+ (1,0) [0|255] ""  DCDC
 SG_ P2D_DLoadInfo_Data2 : 16|8@1+ (1,0) [0|255] ""  DCDC
 SG_ P2D_DLoadInfo_Data3 : 24|8@1+ (1,0) [0|255] ""  DCDC
 SG_ P2D_DLoadInfo_Data4 : 32|8@1+ (1,0) [0|255] ""  DCDC
 SG_ P2D_DLoadInfo_Data5 : 40|8@1+ (1,0) [0|255] ""  DCDC
 SG_ P2D_DLoadInfo_Data6 : 48|8@1+ (1,0) [0|255] ""  DCDC
 SG_ P2D_DLoadInfo_Data7 : 56|8@1+ (1,0) [0|255] ""  DCDC

BO_ 2149220183 P2D_DLoadInfo__23: 8 PC
 SG_ P2D_DLoadInfo_Data0 : 0|8@1+ (1,0) [0|255] ""  DCDC
 SG_ P2D_DLoadInfo_Data1 : 8|8@1+ (1,0) [0|255] ""  DCDC
 SG_ P2D_DLoadInfo_Data2 : 16|8@1+ (1,0) [0|255] ""  DCDC
 SG_ P2D_DLoadInfo_Data3 : 24|8@1+ (1,0) [0|255] ""  DCDC
 SG_ P2D_DLoadInfo_Data4 : 32|8@1+ (1,0) [0|255] ""  DCDC
 SG_ P2D_DLoadInfo_Data5 : 40|8@1+ (1,0) [0|255] ""  DCDC
 SG_ P2D_DLoadInfo_Data6 : 48|8@1+ (1,0) [0|255] ""  DCDC
 SG_ P2D_DLoadInfo_Data7 : 56|8@1+ (1,0) [0|255] ""  DCDC

BO_ 2149220184 P2D_DLoadInfo__24: 8 PC
 SG_ P2D_DLoadInfo_Data0 : 0|8@1+ (1,0) [0|255] ""  DCDC
 SG_ P2D_DLoadInfo_Data1 : 8|8@1+ (1,0) [0|255] ""  DCDC
 SG_ P2D_DLoadInfo_Data2 : 16|8@1+ (1,0) [0|255] ""  DCDC
 SG_ P2D_DLoadInfo_Data3 : 24|8@1+ (1,0) [0|255] ""  DCDC
 SG_ P2D_DLoadInfo_Data4 : 32|8@1+ (1,0) [0|255] ""  DCDC
 SG_ P2D_DLoadInfo_Data5 : 40|8@1+ (1,0) [0|255] ""  DCDC
 SG_ P2D_DLoadInfo_Data6 : 48|8@1+ (1,0) [0|255] ""  DCDC
 SG_ P2D_DLoadInfo_Data7 : 56|8@1+ (1,0) [0|255] ""  DCDC

BO_ 2149220185 P2D_DLoadInfo__25: 8 PC
 SG_ P2D_DLoadInfo_Data0 : 0|8@1+ (1,0) [0|255] ""  DCDC
 SG_ P2D_DLoadInfo_Data1 : 8|8@1+ (1,0) [0|255] ""  DCDC
 SG_ P2D_DLoadInfo_Data2 : 16|8@1+ (1,0) [0|255] ""  DCDC
 SG_ P2D_DLoadInfo_Data3 : 24|8@1+ (1,0) [0|255] ""  DCDC
 SG_ P2D_DLoadInfo_Data4 : 32|8@1+ (1,0) [0|255] ""  DCDC
 SG_ P2D_DLoadInfo_Data5 : 40|8@1+ (1,0) [0|255] ""  DCDC
 SG_ P2D_DLoadInfo_Data6 : 48|8@1+ (1,0) [0|255] ""  DCDC
 SG_ P2D_DLoadInfo_Data7 : 56|8@1+ (1,0) [0|255] ""  DCDC

BO_ 2149220186 P2D_DLoadInfo__26: 8 PC
 SG_ P2D_DLoadInfo_Data0 : 0|8@1+ (1,0) [0|255] ""  DCDC
 SG_ P2D_DLoadInfo_Data1 : 8|8@1+ (1,0) [0|255] ""  DCDC
 SG_ P2D_DLoadInfo_Data2 : 16|8@1+ (1,0) [0|255] ""  DCDC
 SG_ P2D_DLoadInfo_Data3 : 24|8@1+ (1,0) [0|255] ""  DCDC
 SG_ P2D_DLoadInfo_Data4 : 32|8@1+ (1,0) [0|255] ""  DCDC
 SG_ P2D_DLoadInfo_Data5 : 40|8@1+ (1,0) [0|255] ""  DCDC
 SG_ P2D_DLoadInfo_Data6 : 48|8@1+ (1,0) [0|255] ""  DCDC
 SG_ P2D_DLoadInfo_Data7 : 56|8@1+ (1,0) [0|255] ""  DCDC

BO_ 2149220187 P2D_DLoadInfo__27: 8 PC
 SG_ P2D_DLoadInfo_Data0 : 0|8@1+ (1,0) [0|255] ""  DCDC
 SG_ P2D_DLoadInfo_Data1 : 8|8@1+ (1,0) [0|255] ""  DCDC
 SG_ P2D_DLoadInfo_Data2 : 16|8@1+ (1,0) [0|255] ""  DCDC
 SG_ P2D_DLoadInfo_Data3 : 24|8@1+ (1,0) [0|255] ""  DCDC
 SG_ P2D_DLoadInfo_Data4 : 32|8@1+ (1,0) [0|255] ""  DCDC
 SG_ P2D_DLoadInfo_Data5 : 40|8@1+ (1,0) [0|255] ""  DCDC
 SG_ P2D_DLoadInfo_Data6 : 48|8@1+ (1,0) [0|255] ""  DCDC
 SG_ P2D_DLoadInfo_Data7 : 56|8@1+ (1,0) [0|255] ""  DCDC

BO_ 2149220188 P2D_DLoadInfo__28: 8 PC
 SG_ P2D_DLoadInfo_Data0 : 0|8@1+ (1,0) [0|255] ""  DCDC
 SG_ P2D_DLoadInfo_Data1 : 8|8@1+ (1,0) [0|255] ""  DCDC
 SG_ P2D_DLoadInfo_Data2 : 16|8@1+ (1,0) [0|255] ""  DCDC
 SG_ P2D_DLoadInfo_Data3 : 24|8@1+ (1,0) [0|255] ""  DCDC
 SG_ P2D_DLoadInfo_Data4 : 32|8@1+ (1,0) [0|255] ""  DCDC
 SG_ P2D_DLoadInfo_Data5 : 40|8@1+ (1,0) [0|255] ""  DCDC
 SG_ P2D_DLoadInfo_Data6 : 48|8@1+ (1,0) [0|255] ""  DCDC
 SG_ P2D_DLoadInfo_Data7 : 56|8@1+ (1,0) [0|255] ""  DCDC

BO_ 2149220189 P2D_DLoadInfo__29: 8 PC
 SG_ P2D_DLoadInfo_Data0 : 0|8@1+ (1,0) [0|255] ""  DCDC
 SG_ P2D_DLoadInfo_Data1 : 8|8@1+ (1,0) [0|255] ""  DCDC
 SG_ P2D_DLoadInfo_Data2 : 16|8@1+ (1,0) [0|255] ""  DCDC
 SG_ P2D_DLoadInfo_Data3 : 24|8@1+ (1,0) [0|255] ""  DCDC
 SG_ P2D_DLoadInfo_Data4 : 32|8@1+ (1,0) [0|255] ""  DCDC
 SG_ P2D_DLoadInfo_Data5 : 40|8@1+ (1,0) [0|255] ""  DCDC
 SG_ P2D_DLoadInfo_Data6 : 48|8@1+ (1,0) [0|255] ""  DCDC
 SG_ P2D_DLoadInfo_Data7 : 56|8@1+ (1,0) [0|255] ""  DCDC

BO_ 2149220190 P2D_DLoadInfo__30: 8 PC
 SG_ P2D_DLoadInfo_Data0 : 0|8@1+ (1,0) [0|255] ""  DCDC
 SG_ P2D_DLoadInfo_Data1 : 8|8@1+ (1,0) [0|255] ""  DCDC
 SG_ P2D_DLoadInfo_Data2 : 16|8@1+ (1,0) [0|255] ""  DCDC
 SG_ P2D_DLoadInfo_Data3 : 24|8@1+ (1,0) [0|255] ""  DCDC
 SG_ P2D_DLoadInfo_Data4 : 32|8@1+ (1,0) [0|255] ""  DCDC
 SG_ P2D_DLoadInfo_Data5 : 40|8@1+ (1,0) [0|255] ""  DCDC
 SG_ P2D_DLoadInfo_Data6 : 48|8@1+ (1,0) [0|255] ""  DCDC
 SG_ P2D_DLoadInfo_Data7 : 56|8@1+ (1,0) [0|255] ""  DCDC

BO_ 2149220191 P2D_DLoadInfo__31: 8 PC
 SG_ P2D_DLoadInfo_Data0 : 0|8@1+ (1,0) [0|255] ""  DCDC
 SG_ P2D_DLoadInfo_Data1 : 8|8@1+ (1,0) [0|255] ""  DCDC
 SG_ P2D_DLoadInfo_Data2 : 16|8@1+ (1,0) [0|255] ""  DCDC
 SG_ P2D_DLoadInfo_Data3 : 24|8@1+ (1,0) [0|255] ""  DCDC
 SG_ P2D_DLoadInfo_Data4 : 32|8@1+ (1,0) [0|255] ""  DCDC
 SG_ P2D_DLoadInfo_Data5 : 40|8@1+ (1,0) [0|255] ""  DCDC
 SG_ P2D_DLoadInfo_Data6 : 48|8@1+ (1,0) [0|255] ""  DCDC
 SG_ P2D_DLoadInfo_Data7 : 56|8@1+ (1,0) [0|255] ""  DCDC

BO_ 2149220192 P2D_DLoadInfo__32: 8 PC
 SG_ P2D_DLoadInfo_Data0 : 0|8@1+ (1,0) [0|255] ""  DCDC
 SG_ P2D_DLoadInfo_Data1 : 8|8@1+ (1,0) [0|255] ""  DCDC
 SG_ P2D_DLoadInfo_Data2 : 16|8@1+ (1,0) [0|255] ""  DCDC
 SG_ P2D_DLoadInfo_Data3 : 24|8@1+ (1,0) [0|255] ""  DCDC
 SG_ P2D_DLoadInfo_Data4 : 32|8@1+ (1,0) [0|255] ""  DCDC
 SG_ P2D_DLoadInfo_Data5 : 40|8@1+ (1,0) [0|255] ""  DCDC
 SG_ P2D_DLoadInfo_Data6 : 48|8@1+ (1,0) [0|255] ""  DCDC
 SG_ P2D_DLoadInfo_Data7 : 56|8@1+ (1,0) [0|255] ""  DCDC

BO_ 2149220193 P2D_DLoadInfo__33: 8 PC
 SG_ P2D_DLoadInfo_Data0 : 0|8@1+ (1,0) [0|255] ""  DCDC
 SG_ P2D_DLoadInfo_Data1 : 8|8@1+ (1,0) [0|255] ""  DCDC
 SG_ P2D_DLoadInfo_Data2 : 16|8@1+ (1,0) [0|255] ""  DCDC
 SG_ P2D_DLoadInfo_Data3 : 24|8@1+ (1,0) [0|255] ""  DCDC
 SG_ P2D_DLoadInfo_Data4 : 32|8@1+ (1,0) [0|255] ""  DCDC
 SG_ P2D_DLoadInfo_Data5 : 40|8@1+ (1,0) [0|255] ""  DCDC
 SG_ P2D_DLoadInfo_Data6 : 48|8@1+ (1,0) [0|255] ""  DCDC
 SG_ P2D_DLoadInfo_Data7 : 56|8@1+ (1,0) [0|255] ""  DCDC

BO_ 2149220194 P2D_DLoadInfo__34: 8 PC
 SG_ P2D_DLoadInfo_Data0 : 0|8@1+ (1,0) [0|255] ""  DCDC
 SG_ P2D_DLoadInfo_Data1 : 8|8@1+ (1,0) [0|255] ""  DCDC
 SG_ P2D_DLoadInfo_Data2 : 16|8@1+ (1,0) [0|255] ""  DCDC
 SG_ P2D_DLoadInfo_Data3 : 24|8@1+ (1,0) [0|255] ""  DCDC
 SG_ P2D_DLoadInfo_Data4 : 32|8@1+ (1,0) [0|255] ""  DCDC
 SG_ P2D_DLoadInfo_Data5 : 40|8@1+ (1,0) [0|255] ""  DCDC
 SG_ P2D_DLoadInfo_Data6 : 48|8@1+ (1,0) [0|255] ""  DCDC
 SG_ P2D_DLoadInfo_Data7 : 56|8@1+ (1,0) [0|255] ""  DCDC

BO_ 2149220195 P2D_DLoadInfo__35: 8 PC
 SG_ P2D_DLoadInfo_Data0 : 0|8@1+ (1,0) [0|255] ""  DCDC
 SG_ P2D_DLoadInfo_Data1 : 8|8@1+ (1,0) [0|255] ""  DCDC
 SG_ P2D_DLoadInfo_Data2 : 16|8@1+ (1,0) [0|255] ""  DCDC
 SG_ P2D_DLoadInfo_Data3 : 24|8@1+ (1,0) [0|255] ""  DCDC
 SG_ P2D_DLoadInfo_Data4 : 32|8@1+ (1,0) [0|255] ""  DCDC
 SG_ P2D_DLoadInfo_Data5 : 40|8@1+ (1,0) [0|255] ""  DCDC
 SG_ P2D_DLoadInfo_Data6 : 48|8@1+ (1,0) [0|255] ""  DCDC
 SG_ P2D_DLoadInfo_Data7 : 56|8@1+ (1,0) [0|255] ""  DCDC

BO_ 2149220196 P2D_DLoadInfo__36: 8 PC
 SG_ P2D_DLoadInfo_Data0 : 0|8@1+ (1,0) [0|255] ""  DCDC
 SG_ P2D_DLoadInfo_Data1 : 8|8@1+ (1,0) [0|255] ""  DCDC
 SG_ P2D_DLoadInfo_Data2 : 16|8@1+ (1,0) [0|255] ""  DCDC
 SG_ P2D_DLoadInfo_Data3 : 24|8@1+ (1,0) [0|255] ""  DCDC
 SG_ P2D_DLoadInfo_Data4 : 32|8@1+ (1,0) [0|255] ""  DCDC
 SG_ P2D_DLoadInfo_Data5 : 40|8@1+ (1,0) [0|255] ""  DCDC
 SG_ P2D_DLoadInfo_Data6 : 48|8@1+ (1,0) [0|255] ""  DCDC
 SG_ P2D_DLoadInfo_Data7 : 56|8@1+ (1,0) [0|255] ""  DCDC

BO_ 2149220197 P2D_DLoadInfo__37: 8 PC
 SG_ P2D_DLoadInfo_Data0 : 0|8@1+ (1,0) [0|255] ""  DCDC
 SG_ P2D_DLoadInfo_Data1 : 8|8@1+ (1,0) [0|255] ""  DCDC
 SG_ P2D_DLoadInfo_Data2 : 16|8@1+ (1,0) [0|255] ""  DCDC
 SG_ P2D_DLoadInfo_Data3 : 24|8@1+ (1,0) [0|255] ""  DCDC
 SG_ P2D_DLoadInfo_Data4 : 32|8@1+ (1,0) [0|255] ""  DCDC
 SG_ P2D_DLoadInfo_Data5 : 40|8@1+ (1,0) [0|255] ""  DCDC
 SG_ P2D_DLoadInfo_Data6 : 48|8@1+ (1,0) [0|255] ""  DCDC
 SG_ P2D_DLoadInfo_Data7 : 56|8@1+ (1,0) [0|255] ""  DCDC

BO_ 2149220198 P2D_DLoadInfo__38: 8 PC
 SG_ P2D_DLoadInfo_Data0 : 0|8@1+ (1,0) [0|255] ""  DCDC
 SG_ P2D_DLoadInfo_Data1 : 8|8@1+ (1,0) [0|255] ""  DCDC
 SG_ P2D_DLoadInfo_Data2 : 16|8@1+ (1,0) [0|255] ""  DCDC
 SG_ P2D_DLoadInfo_Data3 : 24|8@1+ (1,0) [0|255] ""  DCDC
 SG_ P2D_DLoadInfo_Data4 : 32|8@1+ (1,0) [0|255] ""  DCDC
 SG_ P2D_DLoadInfo_Data5 : 40|8@1+ (1,0) [0|255] ""  DCDC
 SG_ P2D_DLoadInfo_Data6 : 48|8@1+ (1,0) [0|255] ""  DCDC
 SG_ P2D_DLoadInfo_Data7 : 56|8@1+ (1,0) [0|255] ""  DCDC

BO_ 2149220199 P2D_DLoadInfo__39: 8 PC
 SG_ P2D_DLoadInfo_Data0 : 0|8@1+ (1,0) [0|255] ""  DCDC
 SG_ P2D_DLoadInfo_Data1 : 8|8@1+ (1,0) [0|255] ""  DCDC
 SG_ P2D_DLoadInfo_Data2 : 16|8@1+ (1,0) [0|255] ""  DCDC
 SG_ P2D_DLoadInfo_Data3 : 24|8@1+ (1,0) [0|255] ""  DCDC
 SG_ P2D_DLoadInfo_Data4 : 32|8@1+ (1,0) [0|255] ""  DCDC
 SG_ P2D_DLoadInfo_Data5 : 40|8@1+ (1,0) [0|255] ""  DCDC
 SG_ P2D_DLoadInfo_Data6 : 48|8@1+ (1,0) [0|255] ""  DCDC
 SG_ P2D_DLoadInfo_Data7 : 56|8@1+ (1,0) [0|255] ""  DCDC

BO_ 2149220200 P2D_DLoadInfo__40: 8 PC
 SG_ P2D_DLoadInfo_Data0 : 0|8@1+ (1,0) [0|255] ""  DCDC
 SG_ P2D_DLoadInfo_Data1 : 8|8@1+ (1,0) [0|255] ""  DCDC
 SG_ P2D_DLoadInfo_Data2 : 16|8@1+ (1,0) [0|255] ""  DCDC
 SG_ P2D_DLoadInfo_Data3 : 24|8@1+ (1,0) [0|255] ""  DCDC
 SG_ P2D_DLoadInfo_Data4 : 32|8@1+ (1,0) [0|255] ""  DCDC
 SG_ P2D_DLoadInfo_Data5 : 40|8@1+ (1,0) [0|255] ""  DCDC
 SG_ P2D_DLoadInfo_Data6 : 48|8@1+ (1,0) [0|255] ""  DCDC
 SG_ P2D_DLoadInfo_Data7 : 56|8@1+ (1,0) [0|255] ""  DCDC

BO_ 2149220201 P2D_DLoadInfo__41: 8 PC
 SG_ P2D_DLoadInfo_Data0 : 0|8@1+ (1,0) [0|255] ""  DCDC
 SG_ P2D_DLoadInfo_Data1 : 8|8@1+ (1,0) [0|255] ""  DCDC
 SG_ P2D_DLoadInfo_Data2 : 16|8@1+ (1,0) [0|255] ""  DCDC
 SG_ P2D_DLoadInfo_Data3 : 24|8@1+ (1,0) [0|255] ""  DCDC
 SG_ P2D_DLoadInfo_Data4 : 32|8@1+ (1,0) [0|255] ""  DCDC
 SG_ P2D_DLoadInfo_Data5 : 40|8@1+ (1,0) [0|255] ""  DCDC
 SG_ P2D_DLoadInfo_Data6 : 48|8@1+ (1,0) [0|255] ""  DCDC
 SG_ P2D_DLoadInfo_Data7 : 56|8@1+ (1,0) [0|255] ""  DCDC

BO_ 2149220202 P2D_DLoadInfo__42: 8 PC
 SG_ P2D_DLoadInfo_Data0 : 0|8@1+ (1,0) [0|255] ""  DCDC
 SG_ P2D_DLoadInfo_Data1 : 8|8@1+ (1,0) [0|255] ""  DCDC
 SG_ P2D_DLoadInfo_Data2 : 16|8@1+ (1,0) [0|255] ""  DCDC
 SG_ P2D_DLoadInfo_Data3 : 24|8@1+ (1,0) [0|255] ""  DCDC
 SG_ P2D_DLoadInfo_Data4 : 32|8@1+ (1,0) [0|255] ""  DCDC
 SG_ P2D_DLoadInfo_Data5 : 40|8@1+ (1,0) [0|255] ""  DCDC
 SG_ P2D_DLoadInfo_Data6 : 48|8@1+ (1,0) [0|255] ""  DCDC
 SG_ P2D_DLoadInfo_Data7 : 56|8@1+ (1,0) [0|255] ""  DCDC

BO_ 2149220203 P2D_DLoadInfo__43: 8 PC
 SG_ P2D_DLoadInfo_Data0 : 0|8@1+ (1,0) [0|255] ""  DCDC
 SG_ P2D_DLoadInfo_Data1 : 8|8@1+ (1,0) [0|255] ""  DCDC
 SG_ P2D_DLoadInfo_Data2 : 16|8@1+ (1,0) [0|255] ""  DCDC
 SG_ P2D_DLoadInfo_Data3 : 24|8@1+ (1,0) [0|255] ""  DCDC
 SG_ P2D_DLoadInfo_Data4 : 32|8@1+ (1,0) [0|255] ""  DCDC
 SG_ P2D_DLoadInfo_Data5 : 40|8@1+ (1,0) [0|255] ""  DCDC
 SG_ P2D_DLoadInfo_Data6 : 48|8@1+ (1,0) [0|255] ""  DCDC
 SG_ P2D_DLoadInfo_Data7 : 56|8@1+ (1,0) [0|255] ""  DCDC

BO_ 2149220204 P2D_DLoadInfo__44: 8 PC
 SG_ P2D_DLoadInfo_Data0 : 0|8@1+ (1,0) [0|255] ""  DCDC
 SG_ P2D_DLoadInfo_Data1 : 8|8@1+ (1,0) [0|255] ""  DCDC
 SG_ P2D_DLoadInfo_Data2 : 16|8@1+ (1,0) [0|255] ""  DCDC
 SG_ P2D_DLoadInfo_Data3 : 24|8@1+ (1,0) [0|255] ""  DCDC
 SG_ P2D_DLoadInfo_Data4 : 32|8@1+ (1,0) [0|255] ""  DCDC
 SG_ P2D_DLoadInfo_Data5 : 40|8@1+ (1,0) [0|255] ""  DCDC
 SG_ P2D_DLoadInfo_Data6 : 48|8@1+ (1,0) [0|255] ""  DCDC
 SG_ P2D_DLoadInfo_Data7 : 56|8@1+ (1,0) [0|255] ""  DCDC

BO_ 2149220205 P2D_DLoadInfo__45: 8 PC
 SG_ P2D_DLoadInfo_Data0 : 0|8@1+ (1,0) [0|255] ""  DCDC
 SG_ P2D_DLoadInfo_Data1 : 8|8@1+ (1,0) [0|255] ""  DCDC
 SG_ P2D_DLoadInfo_Data2 : 16|8@1+ (1,0) [0|255] ""  DCDC
 SG_ P2D_DLoadInfo_Data3 : 24|8@1+ (1,0) [0|255] ""  DCDC
 SG_ P2D_DLoadInfo_Data4 : 32|8@1+ (1,0) [0|255] ""  DCDC
 SG_ P2D_DLoadInfo_Data5 : 40|8@1+ (1,0) [0|255] ""  DCDC
 SG_ P2D_DLoadInfo_Data6 : 48|8@1+ (1,0) [0|255] ""  DCDC
 SG_ P2D_DLoadInfo_Data7 : 56|8@1+ (1,0) [0|255] ""  DCDC

BO_ 2149220206 P2D_DLoadInfo__46: 8 PC
 SG_ P2D_DLoadInfo_Data0 : 0|8@1+ (1,0) [0|255] ""  DCDC
 SG_ P2D_DLoadInfo_Data1 : 8|8@1+ (1,0) [0|255] ""  DCDC
 SG_ P2D_DLoadInfo_Data2 : 16|8@1+ (1,0) [0|255] ""  DCDC
 SG_ P2D_DLoadInfo_Data3 : 24|8@1+ (1,0) [0|255] ""  DCDC
 SG_ P2D_DLoadInfo_Data4 : 32|8@1+ (1,0) [0|255] ""  DCDC
 SG_ P2D_DLoadInfo_Data5 : 40|8@1+ (1,0) [0|255] ""  DCDC
 SG_ P2D_DLoadInfo_Data6 : 48|8@1+ (1,0) [0|255] ""  DCDC
 SG_ P2D_DLoadInfo_Data7 : 56|8@1+ (1,0) [0|255] ""  DCDC

BO_ 2149220207 P2D_DLoadInfo__47: 8 PC
 SG_ P2D_DLoadInfo_Data0 : 0|8@1+ (1,0) [0|255] ""  DCDC
 SG_ P2D_DLoadInfo_Data1 : 8|8@1+ (1,0) [0|255] ""  DCDC
 SG_ P2D_DLoadInfo_Data2 : 16|8@1+ (1,0) [0|255] ""  DCDC
 SG_ P2D_DLoadInfo_Data3 : 24|8@1+ (1,0) [0|255] ""  DCDC
 SG_ P2D_DLoadInfo_Data4 : 32|8@1+ (1,0) [0|255] ""  DCDC
 SG_ P2D_DLoadInfo_Data5 : 40|8@1+ (1,0) [0|255] ""  DCDC
 SG_ P2D_DLoadInfo_Data6 : 48|8@1+ (1,0) [0|255] ""  DCDC
 SG_ P2D_DLoadInfo_Data7 : 56|8@1+ (1,0) [0|255] ""  DCDC

BO_ 2149220208 P2D_DLoadInfo__48: 8 PC
 SG_ P2D_DLoadInfo_Data0 : 0|8@1+ (1,0) [0|255] ""  DCDC
 SG_ P2D_DLoadInfo_Data1 : 8|8@1+ (1,0) [0|255] ""  DCDC
 SG_ P2D_DLoadInfo_Data2 : 16|8@1+ (1,0) [0|255] ""  DCDC
 SG_ P2D_DLoadInfo_Data3 : 24|8@1+ (1,0) [0|255] ""  DCDC
 SG_ P2D_DLoadInfo_Data4 : 32|8@1+ (1,0) [0|255] ""  DCDC
 SG_ P2D_DLoadInfo_Data5 : 40|8@1+ (1,0) [0|255] ""  DCDC
 SG_ P2D_DLoadInfo_Data6 : 48|8@1+ (1,0) [0|255] ""  DCDC
 SG_ P2D_DLoadInfo_Data7 : 56|8@1+ (1,0) [0|255] ""  DCDC

BO_ 2149220209 P2D_DLoadInfo__49: 8 PC
 SG_ P2D_DLoadInfo_Data0 : 0|8@1+ (1,0) [0|255] ""  DCDC
 SG_ P2D_DLoadInfo_Data1 : 8|8@1+ (1,0) [0|255] ""  DCDC
 SG_ P2D_DLoadInfo_Data2 : 16|8@1+ (1,0) [0|255] ""  DCDC
 SG_ P2D_DLoadInfo_Data3 : 24|8@1+ (1,0) [0|255] ""  DCDC
 SG_ P2D_DLoadInfo_Data4 : 32|8@1+ (1,0) [0|255] ""  DCDC
 SG_ P2D_DLoadInfo_Data5 : 40|8@1+ (1,0) [0|255] ""  DCDC
 SG_ P2D_DLoadInfo_Data6 : 48|8@1+ (1,0) [0|255] ""  DCDC
 SG_ P2D_DLoadInfo_Data7 : 56|8@1+ (1,0) [0|255] ""  DCDC

BO_ 2149220210 P2D_DLoadInfo__50: 8 PC
 SG_ P2D_DLoadInfo_Data0 : 0|8@1+ (1,0) [0|255] ""  DCDC
 SG_ P2D_DLoadInfo_Data1 : 8|8@1+ (1,0) [0|255] ""  DCDC
 SG_ P2D_DLoadInfo_Data2 : 16|8@1+ (1,0) [0|255] ""  DCDC
 SG_ P2D_DLoadInfo_Data3 : 24|8@1+ (1,0) [0|255] ""  DCDC
 SG_ P2D_DLoadInfo_Data4 : 32|8@1+ (1,0) [0|255] ""  DCDC
 SG_ P2D_DLoadInfo_Data5 : 40|8@1+ (1,0) [0|255] ""  DCDC
 SG_ P2D_DLoadInfo_Data6 : 48|8@1+ (1,0) [0|255] ""  DCDC
 SG_ P2D_DLoadInfo_Data7 : 56|8@1+ (1,0) [0|255] ""  DCDC

BO_ 2149220211 P2D_DLoadInfo__51: 8 PC
 SG_ P2D_DLoadInfo_Data0 : 0|8@1+ (1,0) [0|255] ""  DCDC
 SG_ P2D_DLoadInfo_Data1 : 8|8@1+ (1,0) [0|255] ""  DCDC
 SG_ P2D_DLoadInfo_Data2 : 16|8@1+ (1,0) [0|255] ""  DCDC
 SG_ P2D_DLoadInfo_Data3 : 24|8@1+ (1,0) [0|255] ""  DCDC
 SG_ P2D_DLoadInfo_Data4 : 32|8@1+ (1,0) [0|255] ""  DCDC
 SG_ P2D_DLoadInfo_Data5 : 40|8@1+ (1,0) [0|255] ""  DCDC
 SG_ P2D_DLoadInfo_Data6 : 48|8@1+ (1,0) [0|255] ""  DCDC
 SG_ P2D_DLoadInfo_Data7 : 56|8@1+ (1,0) [0|255] ""  DCDC

BO_ 2149220212 P2D_DLoadInfo__52: 8 PC
 SG_ P2D_DLoadInfo_Data0 : 0|8@1+ (1,0) [0|255] ""  DCDC
 SG_ P2D_DLoadInfo_Data1 : 8|8@1+ (1,0) [0|255] ""  DCDC
 SG_ P2D_DLoadInfo_Data2 : 16|8@1+ (1,0) [0|255] ""  DCDC
 SG_ P2D_DLoadInfo_Data3 : 24|8@1+ (1,0) [0|255] ""  DCDC
 SG_ P2D_DLoadInfo_Data4 : 32|8@1+ (1,0) [0|255] ""  DCDC
 SG_ P2D_DLoadInfo_Data5 : 40|8@1+ (1,0) [0|255] ""  DCDC
 SG_ P2D_DLoadInfo_Data6 : 48|8@1+ (1,0) [0|255] ""  DCDC
 SG_ P2D_DLoadInfo_Data7 : 56|8@1+ (1,0) [0|255] ""  DCDC

BO_ 2149220213 P2D_DLoadInfo__53: 8 PC
 SG_ P2D_DLoadInfo_Data0 : 0|8@1+ (1,0) [0|255] ""  DCDC
 SG_ P2D_DLoadInfo_Data1 : 8|8@1+ (1,0) [0|255] ""  DCDC
 SG_ P2D_DLoadInfo_Data2 : 16|8@1+ (1,0) [0|255] ""  DCDC
 SG_ P2D_DLoadInfo_Data3 : 24|8@1+ (1,0) [0|255] ""  DCDC
 SG_ P2D_DLoadInfo_Data4 : 32|8@1+ (1,0) [0|255] ""  DCDC
 SG_ P2D_DLoadInfo_Data5 : 40|8@1+ (1,0) [0|255] ""  DCDC
 SG_ P2D_DLoadInfo_Data6 : 48|8@1+ (1,0) [0|255] ""  DCDC
 SG_ P2D_DLoadInfo_Data7 : 56|8@1+ (1,0) [0|255] ""  DCDC

BO_ 2149220214 P2D_DLoadInfo__54: 8 PC
 SG_ P2D_DLoadInfo_Data0 : 0|8@1+ (1,0) [0|255] ""  DCDC
 SG_ P2D_DLoadInfo_Data1 : 8|8@1+ (1,0) [0|255] ""  DCDC
 SG_ P2D_DLoadInfo_Data2 : 16|8@1+ (1,0) [0|255] ""  DCDC
 SG_ P2D_DLoadInfo_Data3 : 24|8@1+ (1,0) [0|255] ""  DCDC
 SG_ P2D_DLoadInfo_Data4 : 32|8@1+ (1,0) [0|255] ""  DCDC
 SG_ P2D_DLoadInfo_Data5 : 40|8@1+ (1,0) [0|255] ""  DCDC
 SG_ P2D_DLoadInfo_Data6 : 48|8@1+ (1,0) [0|255] ""  DCDC
 SG_ P2D_DLoadInfo_Data7 : 56|8@1+ (1,0) [0|255] ""  DCDC

BO_ 2149220215 P2D_DLoadInfo__55: 8 PC
 SG_ P2D_DLoadInfo_Data0 : 0|8@1+ (1,0) [0|255] ""  DCDC
 SG_ P2D_DLoadInfo_Data1 : 8|8@1+ (1,0) [0|255] ""  DCDC
 SG_ P2D_DLoadInfo_Data2 : 16|8@1+ (1,0) [0|255] ""  DCDC
 SG_ P2D_DLoadInfo_Data3 : 24|8@1+ (1,0) [0|255] ""  DCDC
 SG_ P2D_DLoadInfo_Data4 : 32|8@1+ (1,0) [0|255] ""  DCDC
 SG_ P2D_DLoadInfo_Data5 : 40|8@1+ (1,0) [0|255] ""  DCDC
 SG_ P2D_DLoadInfo_Data6 : 48|8@1+ (1,0) [0|255] ""  DCDC
 SG_ P2D_DLoadInfo_Data7 : 56|8@1+ (1,0) [0|255] ""  DCDC

BO_ 2149220216 P2D_DLoadInfo__56: 8 PC
 SG_ P2D_DLoadInfo_Data0 : 0|8@1+ (1,0) [0|255] ""  DCDC
 SG_ P2D_DLoadInfo_Data1 : 8|8@1+ (1,0) [0|255] ""  DCDC
 SG_ P2D_DLoadInfo_Data2 : 16|8@1+ (1,0) [0|255] ""  DCDC
 SG_ P2D_DLoadInfo_Data3 : 24|8@1+ (1,0) [0|255] ""  DCDC
 SG_ P2D_DLoadInfo_Data4 : 32|8@1+ (1,0) [0|255] ""  DCDC
 SG_ P2D_DLoadInfo_Data5 : 40|8@1+ (1,0) [0|255] ""  DCDC
 SG_ P2D_DLoadInfo_Data6 : 48|8@1+ (1,0) [0|255] ""  DCDC
 SG_ P2D_DLoadInfo_Data7 : 56|8@1+ (1,0) [0|255] ""  DCDC

BO_ 2149220217 P2D_DLoadInfo__57: 8 PC
 SG_ P2D_DLoadInfo_Data0 : 0|8@1+ (1,0) [0|255] ""  DCDC
 SG_ P2D_DLoadInfo_Data1 : 8|8@1+ (1,0) [0|255] ""  DCDC
 SG_ P2D_DLoadInfo_Data2 : 16|8@1+ (1,0) [0|255] ""  DCDC
 SG_ P2D_DLoadInfo_Data3 : 24|8@1+ (1,0) [0|255] ""  DCDC
 SG_ P2D_DLoadInfo_Data4 : 32|8@1+ (1,0) [0|255] ""  DCDC
 SG_ P2D_DLoadInfo_Data5 : 40|8@1+ (1,0) [0|255] ""  DCDC
 SG_ P2D_DLoadInfo_Data6 : 48|8@1+ (1,0) [0|255] ""  DCDC
 SG_ P2D_DLoadInfo_Data7 : 56|8@1+ (1,0) [0|255] ""  DCDC

BO_ 2149220218 P2D_DLoadInfo__58: 8 PC
 SG_ P2D_DLoadInfo_Data0 : 0|8@1+ (1,0) [0|255] ""  DCDC
 SG_ P2D_DLoadInfo_Data1 : 8|8@1+ (1,0) [0|255] ""  DCDC
 SG_ P2D_DLoadInfo_Data2 : 16|8@1+ (1,0) [0|255] ""  DCDC
 SG_ P2D_DLoadInfo_Data3 : 24|8@1+ (1,0) [0|255] ""  DCDC
 SG_ P2D_DLoadInfo_Data4 : 32|8@1+ (1,0) [0|255] ""  DCDC
 SG_ P2D_DLoadInfo_Data5 : 40|8@1+ (1,0) [0|255] ""  DCDC
 SG_ P2D_DLoadInfo_Data6 : 48|8@1+ (1,0) [0|255] ""  DCDC
 SG_ P2D_DLoadInfo_Data7 : 56|8@1+ (1,0) [0|255] ""  DCDC

BO_ 2149220219 P2D_DLoadInfo__59: 8 PC
 SG_ P2D_DLoadInfo_Data0 : 0|8@1+ (1,0) [0|255] ""  DCDC
 SG_ P2D_DLoadInfo_Data1 : 8|8@1+ (1,0) [0|255] ""  DCDC
 SG_ P2D_DLoadInfo_Data2 : 16|8@1+ (1,0) [0|255] ""  DCDC
 SG_ P2D_DLoadInfo_Data3 : 24|8@1+ (1,0) [0|255] ""  DCDC
 SG_ P2D_DLoadInfo_Data4 : 32|8@1+ (1,0) [0|255] ""  DCDC
 SG_ P2D_DLoadInfo_Data5 : 40|8@1+ (1,0) [0|255] ""  DCDC
 SG_ P2D_DLoadInfo_Data6 : 48|8@1+ (1,0) [0|255] ""  DCDC
 SG_ P2D_DLoadInfo_Data7 : 56|8@1+ (1,0) [0|255] ""  DCDC

BO_ 2149220220 P2D_DLoadInfo__60: 8 PC
 SG_ P2D_DLoadInfo_Data0 : 0|8@1+ (1,0) [0|255] ""  DCDC
 SG_ P2D_DLoadInfo_Data1 : 8|8@1+ (1,0) [0|255] ""  DCDC
 SG_ P2D_DLoadInfo_Data2 : 16|8@1+ (1,0) [0|255] ""  DCDC
 SG_ P2D_DLoadInfo_Data3 : 24|8@1+ (1,0) [0|255] ""  DCDC
 SG_ P2D_DLoadInfo_Data4 : 32|8@1+ (1,0) [0|255] ""  DCDC
 SG_ P2D_DLoadInfo_Data5 : 40|8@1+ (1,0) [0|255] ""  DCDC
 SG_ P2D_DLoadInfo_Data6 : 48|8@1+ (1,0) [0|255] ""  DCDC
 SG_ P2D_DLoadInfo_Data7 : 56|8@1+ (1,0) [0|255] ""  DCDC

BO_ 2149220221 P2D_DLoadInfo__61: 8 PC
 SG_ P2D_DLoadInfo_Data0 : 0|8@1+ (1,0) [0|255] ""  DCDC
 SG_ P2D_DLoadInfo_Data1 : 8|8@1+ (1,0) [0|255] ""  DCDC
 SG_ P2D_DLoadInfo_Data2 : 16|8@1+ (1,0) [0|255] ""  DCDC
 SG_ P2D_DLoadInfo_Data3 : 24|8@1+ (1,0) [0|255] ""  DCDC
 SG_ P2D_DLoadInfo_Data4 : 32|8@1+ (1,0) [0|255] ""  DCDC
 SG_ P2D_DLoadInfo_Data5 : 40|8@1+ (1,0) [0|255] ""  DCDC
 SG_ P2D_DLoadInfo_Data6 : 48|8@1+ (1,0) [0|255] ""  DCDC
 SG_ P2D_DLoadInfo_Data7 : 56|8@1+ (1,0) [0|255] ""  DCDC

BO_ 2149220222 P2D_DLoadInfo__62: 8 PC
 SG_ P2D_DLoadInfo_Data0 : 0|8@1+ (1,0) [0|255] ""  DCDC
 SG_ P2D_DLoadInfo_Data1 : 8|8@1+ (1,0) [0|255] ""  DCDC
 SG_ P2D_DLoadInfo_Data2 : 16|8@1+ (1,0) [0|255] ""  DCDC
 SG_ P2D_DLoadInfo_Data3 : 24|8@1+ (1,0) [0|255] ""  DCDC
 SG_ P2D_DLoadInfo_Data4 : 32|8@1+ (1,0) [0|255] ""  DCDC
 SG_ P2D_DLoadInfo_Data5 : 40|8@1+ (1,0) [0|255] ""  DCDC
 SG_ P2D_DLoadInfo_Data6 : 48|8@1+ (1,0) [0|255] ""  DCDC
 SG_ P2D_DLoadInfo_Data7 : 56|8@1+ (1,0) [0|255] ""  DCDC

BO_ 2149220223 P2D_DLoadInfo__63: 8 PC
 SG_ P2D_DLoadInfo_Data0 : 0|8@1+ (1,0) [0|255] ""  DCDC
 SG_ P2D_DLoadInfo_Data1 : 8|8@1+ (1,0) [0|255] ""  DCDC
 SG_ P2D_DLoadInfo_Data2 : 16|8@1+ (1,0) [0|255] ""  DCDC
 SG_ P2D_DLoadInfo_Data3 : 24|8@1+ (1,0) [0|255] ""  DCDC
 SG_ P2D_DLoadInfo_Data4 : 32|8@1+ (1,0) [0|255] ""  DCDC
 SG_ P2D_DLoadInfo_Data5 : 40|8@1+ (1,0) [0|255] ""  DCDC
 SG_ P2D_DLoadInfo_Data6 : 48|8@1+ (1,0) [0|255] ""  DCDC
 SG_ P2D_DLoadInfo_Data7 : 56|8@1+ (1,0) [0|255] ""  DCDC

BO_ 2149285697 P2D_PrgData__01: 8 PC
 SG_ P2D_PrgData_Data0 : 0|8@1+ (1,0) [0|255] ""  DCDC
 SG_ P2D_PrgData_Data1 : 8|8@1+ (1,0) [0|255] ""  DCDC
 SG_ P2D_PrgData_Data2 : 16|8@1+ (1,0) [0|255] ""  DCDC
 SG_ P2D_PrgData_Data3 : 24|8@1+ (1,0) [0|255] ""  DCDC
 SG_ P2D_PrgData_Data4 : 32|8@1+ (1,0) [0|255] ""  DCDC
 SG_ P2D_PrgData_Data5 : 40|8@1+ (1,0) [0|255] ""  DCDC
 SG_ P2D_PrgData_Data6 : 48|8@1+ (1,0) [0|255] ""  DCDC
 SG_ P2D_PrgData_Data7 : 56|8@1+ (1,0) [0|255] ""  DCDC

BO_ 2149285698 P2D_PrgData__02: 8 PC
 SG_ P2D_PrgData_Data0 : 0|8@1+ (1,0) [0|255] ""  DCDC
 SG_ P2D_PrgData_Data1 : 8|8@1+ (1,0) [0|255] ""  DCDC
 SG_ P2D_PrgData_Data2 : 16|8@1+ (1,0) [0|255] ""  DCDC
 SG_ P2D_PrgData_Data3 : 24|8@1+ (1,0) [0|255] ""  DCDC
 SG_ P2D_PrgData_Data4 : 32|8@1+ (1,0) [0|255] ""  DCDC
 SG_ P2D_PrgData_Data5 : 40|8@1+ (1,0) [0|255] ""  DCDC
 SG_ P2D_PrgData_Data6 : 48|8@1+ (1,0) [0|255] ""  DCDC
 SG_ P2D_PrgData_Data7 : 56|8@1+ (1,0) [0|255] ""  DCDC

BO_ 2149285699 P2D_PrgData__03: 8 PC
 SG_ P2D_PrgData_Data0 : 0|8@1+ (1,0) [0|255] ""  DCDC
 SG_ P2D_PrgData_Data1 : 8|8@1+ (1,0) [0|255] ""  DCDC
 SG_ P2D_PrgData_Data2 : 16|8@1+ (1,0) [0|255] ""  DCDC
 SG_ P2D_PrgData_Data3 : 24|8@1+ (1,0) [0|255] ""  DCDC
 SG_ P2D_PrgData_Data4 : 32|8@1+ (1,0) [0|255] ""  DCDC
 SG_ P2D_PrgData_Data5 : 40|8@1+ (1,0) [0|255] ""  DCDC
 SG_ P2D_PrgData_Data6 : 48|8@1+ (1,0) [0|255] ""  DCDC
 SG_ P2D_PrgData_Data7 : 56|8@1+ (1,0) [0|255] ""  DCDC

BO_ 2149285700 P2D_PrgData__04: 8 PC
 SG_ P2D_PrgData_Data0 : 0|8@1+ (1,0) [0|255] ""  DCDC
 SG_ P2D_PrgData_Data1 : 8|8@1+ (1,0) [0|255] ""  DCDC
 SG_ P2D_PrgData_Data2 : 16|8@1+ (1,0) [0|255] ""  DCDC
 SG_ P2D_PrgData_Data3 : 24|8@1+ (1,0) [0|255] ""  DCDC
 SG_ P2D_PrgData_Data4 : 32|8@1+ (1,0) [0|255] ""  DCDC
 SG_ P2D_PrgData_Data5 : 40|8@1+ (1,0) [0|255] ""  DCDC
 SG_ P2D_PrgData_Data6 : 48|8@1+ (1,0) [0|255] ""  DCDC
 SG_ P2D_PrgData_Data7 : 56|8@1+ (1,0) [0|255] ""  DCDC

BO_ 2149285701 P2D_PrgData__05: 8 PC
 SG_ P2D_PrgData_Data0 : 0|8@1+ (1,0) [0|255] ""  DCDC
 SG_ P2D_PrgData_Data1 : 8|8@1+ (1,0) [0|255] ""  DCDC
 SG_ P2D_PrgData_Data2 : 16|8@1+ (1,0) [0|255] ""  DCDC
 SG_ P2D_PrgData_Data3 : 24|8@1+ (1,0) [0|255] ""  DCDC
 SG_ P2D_PrgData_Data4 : 32|8@1+ (1,0) [0|255] ""  DCDC
 SG_ P2D_PrgData_Data5 : 40|8@1+ (1,0) [0|255] ""  DCDC
 SG_ P2D_PrgData_Data6 : 48|8@1+ (1,0) [0|255] ""  DCDC
 SG_ P2D_PrgData_Data7 : 56|8@1+ (1,0) [0|255] ""  DCDC

BO_ 2149285702 P2D_PrgData__06: 8 PC
 SG_ P2D_PrgData_Data0 : 0|8@1+ (1,0) [0|255] ""  DCDC
 SG_ P2D_PrgData_Data1 : 8|8@1+ (1,0) [0|255] ""  DCDC
 SG_ P2D_PrgData_Data2 : 16|8@1+ (1,0) [0|255] ""  DCDC
 SG_ P2D_PrgData_Data3 : 24|8@1+ (1,0) [0|255] ""  DCDC
 SG_ P2D_PrgData_Data4 : 32|8@1+ (1,0) [0|255] ""  DCDC
 SG_ P2D_PrgData_Data5 : 40|8@1+ (1,0) [0|255] ""  DCDC
 SG_ P2D_PrgData_Data6 : 48|8@1+ (1,0) [0|255] ""  DCDC
 SG_ P2D_PrgData_Data7 : 56|8@1+ (1,0) [0|255] ""  DCDC

BO_ 2149285703 P2D_PrgData__07: 8 PC
 SG_ P2D_PrgData_Data0 : 0|8@1+ (1,0) [0|255] ""  DCDC
 SG_ P2D_PrgData_Data1 : 8|8@1+ (1,0) [0|255] ""  DCDC
 SG_ P2D_PrgData_Data2 : 16|8@1+ (1,0) [0|255] ""  DCDC
 SG_ P2D_PrgData_Data3 : 24|8@1+ (1,0) [0|255] ""  DCDC
 SG_ P2D_PrgData_Data4 : 32|8@1+ (1,0) [0|255] ""  DCDC
 SG_ P2D_PrgData_Data5 : 40|8@1+ (1,0) [0|255] ""  DCDC
 SG_ P2D_PrgData_Data6 : 48|8@1+ (1,0) [0|255] ""  DCDC
 SG_ P2D_PrgData_Data7 : 56|8@1+ (1,0) [0|255] ""  DCDC

BO_ 2149285704 P2D_PrgData__08: 8 PC
 SG_ P2D_PrgData_Data0 : 0|8@1+ (1,0) [0|255] ""  DCDC
 SG_ P2D_PrgData_Data1 : 8|8@1+ (1,0) [0|255] ""  DCDC
 SG_ P2D_PrgData_Data2 : 16|8@1+ (1,0) [0|255] ""  DCDC
 SG_ P2D_PrgData_Data3 : 24|8@1+ (1,0) [0|255] ""  DCDC
 SG_ P2D_PrgData_Data4 : 32|8@1+ (1,0) [0|255] ""  DCDC
 SG_ P2D_PrgData_Data5 : 40|8@1+ (1,0) [0|255] ""  DCDC
 SG_ P2D_PrgData_Data6 : 48|8@1+ (1,0) [0|255] ""  DCDC
 SG_ P2D_PrgData_Data7 : 56|8@1+ (1,0) [0|255] ""  DCDC

BO_ 2149285705 P2D_PrgData__09: 8 PC
 SG_ P2D_PrgData_Data0 : 0|8@1+ (1,0) [0|255] ""  DCDC
 SG_ P2D_PrgData_Data1 : 8|8@1+ (1,0) [0|255] ""  DCDC
 SG_ P2D_PrgData_Data2 : 16|8@1+ (1,0) [0|255] ""  DCDC
 SG_ P2D_PrgData_Data3 : 24|8@1+ (1,0) [0|255] ""  DCDC
 SG_ P2D_PrgData_Data4 : 32|8@1+ (1,0) [0|255] ""  DCDC
 SG_ P2D_PrgData_Data5 : 40|8@1+ (1,0) [0|255] ""  DCDC
 SG_ P2D_PrgData_Data6 : 48|8@1+ (1,0) [0|255] ""  DCDC
 SG_ P2D_PrgData_Data7 : 56|8@1+ (1,0) [0|255] ""  DCDC

BO_ 2149285706 P2D_PrgData__10: 8 PC
 SG_ P2D_PrgData_Data0 : 0|8@1+ (1,0) [0|255] ""  DCDC
 SG_ P2D_PrgData_Data1 : 8|8@1+ (1,0) [0|255] ""  DCDC
 SG_ P2D_PrgData_Data2 : 16|8@1+ (1,0) [0|255] ""  DCDC
 SG_ P2D_PrgData_Data3 : 24|8@1+ (1,0) [0|255] ""  DCDC
 SG_ P2D_PrgData_Data4 : 32|8@1+ (1,0) [0|255] ""  DCDC
 SG_ P2D_PrgData_Data5 : 40|8@1+ (1,0) [0|255] ""  DCDC
 SG_ P2D_PrgData_Data6 : 48|8@1+ (1,0) [0|255] ""  DCDC
 SG_ P2D_PrgData_Data7 : 56|8@1+ (1,0) [0|255] ""  DCDC

BO_ 2149285707 P2D_PrgData__11: 8 PC
 SG_ P2D_PrgData_Data0 : 0|8@1+ (1,0) [0|255] ""  DCDC
 SG_ P2D_PrgData_Data1 : 8|8@1+ (1,0) [0|255] ""  DCDC
 SG_ P2D_PrgData_Data2 : 16|8@1+ (1,0) [0|255] ""  DCDC
 SG_ P2D_PrgData_Data3 : 24|8@1+ (1,0) [0|255] ""  DCDC
 SG_ P2D_PrgData_Data4 : 32|8@1+ (1,0) [0|255] ""  DCDC
 SG_ P2D_PrgData_Data5 : 40|8@1+ (1,0) [0|255] ""  DCDC
 SG_ P2D_PrgData_Data6 : 48|8@1+ (1,0) [0|255] ""  DCDC
 SG_ P2D_PrgData_Data7 : 56|8@1+ (1,0) [0|255] ""  DCDC

BO_ 2149285708 P2D_PrgData__12: 8 PC
 SG_ P2D_PrgData_Data0 : 0|8@1+ (1,0) [0|255] ""  DCDC
 SG_ P2D_PrgData_Data1 : 8|8@1+ (1,0) [0|255] ""  DCDC
 SG_ P2D_PrgData_Data2 : 16|8@1+ (1,0) [0|255] ""  DCDC
 SG_ P2D_PrgData_Data3 : 24|8@1+ (1,0) [0|255] ""  DCDC
 SG_ P2D_PrgData_Data4 : 32|8@1+ (1,0) [0|255] ""  DCDC
 SG_ P2D_PrgData_Data5 : 40|8@1+ (1,0) [0|255] ""  DCDC
 SG_ P2D_PrgData_Data6 : 48|8@1+ (1,0) [0|255] ""  DCDC
 SG_ P2D_PrgData_Data7 : 56|8@1+ (1,0) [0|255] ""  DCDC

BO_ 2149285709 P2D_PrgData__13: 8 PC
 SG_ P2D_PrgData_Data0 : 0|8@1+ (1,0) [0|255] ""  DCDC
 SG_ P2D_PrgData_Data1 : 8|8@1+ (1,0) [0|255] ""  DCDC
 SG_ P2D_PrgData_Data2 : 16|8@1+ (1,0) [0|255] ""  DCDC
 SG_ P2D_PrgData_Data3 : 24|8@1+ (1,0) [0|255] ""  DCDC
 SG_ P2D_PrgData_Data4 : 32|8@1+ (1,0) [0|255] ""  DCDC
 SG_ P2D_PrgData_Data5 : 40|8@1+ (1,0) [0|255] ""  DCDC
 SG_ P2D_PrgData_Data6 : 48|8@1+ (1,0) [0|255] ""  DCDC
 SG_ P2D_PrgData_Data7 : 56|8@1+ (1,0) [0|255] ""  DCDC

BO_ 2149285710 P2D_PrgData__14: 8 PC
 SG_ P2D_PrgData_Data0 : 0|8@1+ (1,0) [0|255] ""  DCDC
 SG_ P2D_PrgData_Data1 : 8|8@1+ (1,0) [0|255] ""  DCDC
 SG_ P2D_PrgData_Data2 : 16|8@1+ (1,0) [0|255] ""  DCDC
 SG_ P2D_PrgData_Data3 : 24|8@1+ (1,0) [0|255] ""  DCDC
 SG_ P2D_PrgData_Data4 : 32|8@1+ (1,0) [0|255] ""  DCDC
 SG_ P2D_PrgData_Data5 : 40|8@1+ (1,0) [0|255] ""  DCDC
 SG_ P2D_PrgData_Data6 : 48|8@1+ (1,0) [0|255] ""  DCDC
 SG_ P2D_PrgData_Data7 : 56|8@1+ (1,0) [0|255] ""  DCDC

BO_ 2149285711 P2D_PrgData__15: 8 PC
 SG_ P2D_PrgData_Data0 : 0|8@1+ (1,0) [0|255] ""  DCDC
 SG_ P2D_PrgData_Data1 : 8|8@1+ (1,0) [0|255] ""  DCDC
 SG_ P2D_PrgData_Data2 : 16|8@1+ (1,0) [0|255] ""  DCDC
 SG_ P2D_PrgData_Data3 : 24|8@1+ (1,0) [0|255] ""  DCDC
 SG_ P2D_PrgData_Data4 : 32|8@1+ (1,0) [0|255] ""  DCDC
 SG_ P2D_PrgData_Data5 : 40|8@1+ (1,0) [0|255] ""  DCDC
 SG_ P2D_PrgData_Data6 : 48|8@1+ (1,0) [0|255] ""  DCDC
 SG_ P2D_PrgData_Data7 : 56|8@1+ (1,0) [0|255] ""  DCDC

BO_ 2149285712 P2D_PrgData__16: 8 PC
 SG_ P2D_PrgData_Data0 : 0|8@1+ (1,0) [0|255] ""  DCDC
 SG_ P2D_PrgData_Data1 : 8|8@1+ (1,0) [0|255] ""  DCDC
 SG_ P2D_PrgData_Data2 : 16|8@1+ (1,0) [0|255] ""  DCDC
 SG_ P2D_PrgData_Data3 : 24|8@1+ (1,0) [0|255] ""  DCDC
 SG_ P2D_PrgData_Data4 : 32|8@1+ (1,0) [0|255] ""  DCDC
 SG_ P2D_PrgData_Data5 : 40|8@1+ (1,0) [0|255] ""  DCDC
 SG_ P2D_PrgData_Data6 : 48|8@1+ (1,0) [0|255] ""  DCDC
 SG_ P2D_PrgData_Data7 : 56|8@1+ (1,0) [0|255] ""  DCDC

BO_ 2149285713 P2D_PrgData__17: 8 PC
 SG_ P2D_PrgData_Data0 : 0|8@1+ (1,0) [0|255] ""  DCDC
 SG_ P2D_PrgData_Data1 : 8|8@1+ (1,0) [0|255] ""  DCDC
 SG_ P2D_PrgData_Data2 : 16|8@1+ (1,0) [0|255] ""  DCDC
 SG_ P2D_PrgData_Data3 : 24|8@1+ (1,0) [0|255] ""  DCDC
 SG_ P2D_PrgData_Data4 : 32|8@1+ (1,0) [0|255] ""  DCDC
 SG_ P2D_PrgData_Data5 : 40|8@1+ (1,0) [0|255] ""  DCDC
 SG_ P2D_PrgData_Data6 : 48|8@1+ (1,0) [0|255] ""  DCDC
 SG_ P2D_PrgData_Data7 : 56|8@1+ (1,0) [0|255] ""  DCDC

BO_ 2149285714 P2D_PrgData__18: 8 PC
 SG_ P2D_PrgData_Data0 : 0|8@1+ (1,0) [0|255] ""  DCDC
 SG_ P2D_PrgData_Data1 : 8|8@1+ (1,0) [0|255] ""  DCDC
 SG_ P2D_PrgData_Data2 : 16|8@1+ (1,0) [0|255] ""  DCDC
 SG_ P2D_PrgData_Data3 : 24|8@1+ (1,0) [0|255] ""  DCDC
 SG_ P2D_PrgData_Data4 : 32|8@1+ (1,0) [0|255] ""  DCDC
 SG_ P2D_PrgData_Data5 : 40|8@1+ (1,0) [0|255] ""  DCDC
 SG_ P2D_PrgData_Data6 : 48|8@1+ (1,0) [0|255] ""  DCDC
 SG_ P2D_PrgData_Data7 : 56|8@1+ (1,0) [0|255] ""  DCDC

BO_ 2149285715 P2D_PrgData__19: 8 PC
 SG_ P2D_PrgData_Data0 : 0|8@1+ (1,0) [0|255] ""  DCDC
 SG_ P2D_PrgData_Data1 : 8|8@1+ (1,0) [0|255] ""  DCDC
 SG_ P2D_PrgData_Data2 : 16|8@1+ (1,0) [0|255] ""  DCDC
 SG_ P2D_PrgData_Data3 : 24|8@1+ (1,0) [0|255] ""  DCDC
 SG_ P2D_PrgData_Data4 : 32|8@1+ (1,0) [0|255] ""  DCDC
 SG_ P2D_PrgData_Data5 : 40|8@1+ (1,0) [0|255] ""  DCDC
 SG_ P2D_PrgData_Data6 : 48|8@1+ (1,0) [0|255] ""  DCDC
 SG_ P2D_PrgData_Data7 : 56|8@1+ (1,0) [0|255] ""  DCDC

BO_ 2149285716 P2D_PrgData__20: 8 PC
 SG_ P2D_PrgData_Data0 : 0|8@1+ (1,0) [0|255] ""  DCDC
 SG_ P2D_PrgData_Data1 : 8|8@1+ (1,0) [0|255] ""  DCDC
 SG_ P2D_PrgData_Data2 : 16|8@1+ (1,0) [0|255] ""  DCDC
 SG_ P2D_PrgData_Data3 : 24|8@1+ (1,0) [0|255] ""  DCDC
 SG_ P2D_PrgData_Data4 : 32|8@1+ (1,0) [0|255] ""  DCDC
 SG_ P2D_PrgData_Data5 : 40|8@1+ (1,0) [0|255] ""  DCDC
 SG_ P2D_PrgData_Data6 : 48|8@1+ (1,0) [0|255] ""  DCDC
 SG_ P2D_PrgData_Data7 : 56|8@1+ (1,0) [0|255] ""  DCDC

BO_ 2149285717 P2D_PrgData__21: 8 PC
 SG_ P2D_PrgData_Data0 : 0|8@1+ (1,0) [0|255] ""  DCDC
 SG_ P2D_PrgData_Data1 : 8|8@1+ (1,0) [0|255] ""  DCDC
 SG_ P2D_PrgData_Data2 : 16|8@1+ (1,0) [0|255] ""  DCDC
 SG_ P2D_PrgData_Data3 : 24|8@1+ (1,0) [0|255] ""  DCDC
 SG_ P2D_PrgData_Data4 : 32|8@1+ (1,0) [0|255] ""  DCDC
 SG_ P2D_PrgData_Data5 : 40|8@1+ (1,0) [0|255] ""  DCDC
 SG_ P2D_PrgData_Data6 : 48|8@1+ (1,0) [0|255] ""  DCDC
 SG_ P2D_PrgData_Data7 : 56|8@1+ (1,0) [0|255] ""  DCDC

BO_ 2149285718 P2D_PrgData__22: 8 PC
 SG_ P2D_PrgData_Data0 : 0|8@1+ (1,0) [0|255] ""  DCDC
 SG_ P2D_PrgData_Data1 : 8|8@1+ (1,0) [0|255] ""  DCDC
 SG_ P2D_PrgData_Data2 : 16|8@1+ (1,0) [0|255] ""  DCDC
 SG_ P2D_PrgData_Data3 : 24|8@1+ (1,0) [0|255] ""  DCDC
 SG_ P2D_PrgData_Data4 : 32|8@1+ (1,0) [0|255] ""  DCDC
 SG_ P2D_PrgData_Data5 : 40|8@1+ (1,0) [0|255] ""  DCDC
 SG_ P2D_PrgData_Data6 : 48|8@1+ (1,0) [0|255] ""  DCDC
 SG_ P2D_PrgData_Data7 : 56|8@1+ (1,0) [0|255] ""  DCDC

BO_ 2149285719 P2D_PrgData__23: 8 PC
 SG_ P2D_PrgData_Data0 : 0|8@1+ (1,0) [0|255] ""  DCDC
 SG_ P2D_PrgData_Data1 : 8|8@1+ (1,0) [0|255] ""  DCDC
 SG_ P2D_PrgData_Data2 : 16|8@1+ (1,0) [0|255] ""  DCDC
 SG_ P2D_PrgData_Data3 : 24|8@1+ (1,0) [0|255] ""  DCDC
 SG_ P2D_PrgData_Data4 : 32|8@1+ (1,0) [0|255] ""  DCDC
 SG_ P2D_PrgData_Data5 : 40|8@1+ (1,0) [0|255] ""  DCDC
 SG_ P2D_PrgData_Data6 : 48|8@1+ (1,0) [0|255] ""  DCDC
 SG_ P2D_PrgData_Data7 : 56|8@1+ (1,0) [0|255] ""  DCDC

BO_ 2149285720 P2D_PrgData__24: 8 PC
 SG_ P2D_PrgData_Data0 : 0|8@1+ (1,0) [0|255] ""  DCDC
 SG_ P2D_PrgData_Data1 : 8|8@1+ (1,0) [0|255] ""  DCDC
 SG_ P2D_PrgData_Data2 : 16|8@1+ (1,0) [0|255] ""  DCDC
 SG_ P2D_PrgData_Data3 : 24|8@1+ (1,0) [0|255] ""  DCDC
 SG_ P2D_PrgData_Data4 : 32|8@1+ (1,0) [0|255] ""  DCDC
 SG_ P2D_PrgData_Data5 : 40|8@1+ (1,0) [0|255] ""  DCDC
 SG_ P2D_PrgData_Data6 : 48|8@1+ (1,0) [0|255] ""  DCDC
 SG_ P2D_PrgData_Data7 : 56|8@1+ (1,0) [0|255] ""  DCDC

CM_ SG_ 2149089121 P2D_BUCK_PHY_TX_Byte1_33 "依据CAN下载协议";
CM_ SG_ 2149089121 P2D_BUCK_PHY_TX_Byte2_33 "依据CAN下载协议";
CM_ SG_ 2149089121 P2D_BUCK_PHY_TX_Byte3_33 "依据CAN下载协议";
CM_ SG_ 2149089121 P2D_BUCK_PHY_TX_Byte4_33 "依据CAN下载协议";
CM_ SG_ 2149089121 P2D_BUCK_PHY_TX_Byte5_33 "依据CAN下载协议";
CM_ SG_ 2149089121 P2D_BUCK_PHY_TX_Byte6_33 "依据CAN下载协议";
CM_ SG_ 2149089121 P2D_BUCK_PHY_TX_Byte7_33 "依据CAN下载协议";
CM_ SG_ 2149089121 P2D_BUCK_PHY_TX_Byte8_33 "依据CAN下载协议";
CM_ SG_ 2149089122 P2D_BUCK_PHY_TX_Byte1_34 "依据CAN下载协议";
CM_ SG_ 2149089122 P2D_BUCK_PHY_TX_Byte2_34 "依据CAN下载协议";
CM_ SG_ 2149089122 P2D_BUCK_PHY_TX_Byte3_34 "依据CAN下载协议";
CM_ SG_ 2149089122 P2D_BUCK_PHY_TX_Byte4_34 "依据CAN下载协议";
CM_ SG_ 2149089122 P2D_BUCK_PHY_TX_Byte5_34 "依据CAN下载协议";
CM_ SG_ 2149089122 P2D_BUCK_PHY_TX_Byte6_34 "依据CAN下载协议";
CM_ SG_ 2149089122 P2D_BUCK_PHY_TX_Byte7_34 "依据CAN下载协议";
CM_ SG_ 2149089122 P2D_BUCK_PHY_TX_Byte8_34 "依据CAN下载协议";
CM_ SG_ 2149089123 P2D_BUCK_PHY_TX_Byte1_35 "依据CAN下载协议";
CM_ SG_ 2149089123 P2D_BUCK_PHY_TX_Byte2_35 "依据CAN下载协议";
CM_ SG_ 2149089123 P2D_BUCK_PHY_TX_Byte3_35 "依据CAN下载协议";
CM_ SG_ 2149089123 P2D_BUCK_PHY_TX_Byte4_35 "依据CAN下载协议";
CM_ SG_ 2149089123 P2D_BUCK_PHY_TX_Byte5_35 "依据CAN下载协议";
CM_ SG_ 2149089123 P2D_BUCK_PHY_TX_Byte6_35 "依据CAN下载协议";
CM_ SG_ 2149089123 P2D_BUCK_PHY_TX_Byte7_35 "依据CAN下载协议";
CM_ SG_ 2149089123 P2D_BUCK_PHY_TX_Byte8_35 "依据CAN下载协议";
CM_ SG_ 2149089124 P2D_BUCK_PHY_TX_Byte1_36 "依据CAN下载协议";
CM_ SG_ 2149089124 P2D_BUCK_PHY_TX_Byte2_36 "依据CAN下载协议";
CM_ SG_ 2149089124 P2D_BUCK_PHY_TX_Byte3_36 "依据CAN下载协议";
CM_ SG_ 2149089124 P2D_BUCK_PHY_TX_Byte4_36 "依据CAN下载协议";
CM_ SG_ 2149089124 P2D_BUCK_PHY_TX_Byte5_36 "依据CAN下载协议";
CM_ SG_ 2149089124 P2D_BUCK_PHY_TX_Byte6_36 "依据CAN下载协议";
CM_ SG_ 2149089124 P2D_BUCK_PHY_TX_Byte7_36 "依据CAN下载协议";
CM_ SG_ 2149089124 P2D_BUCK_PHY_TX_Byte8_36 "依据CAN下载协议";
CM_ SG_ 2149089125 P2D_BUCK_PHY_TX_Byte1_37 "依据CAN下载协议";
CM_ SG_ 2149089125 P2D_BUCK_PHY_TX_Byte2_37 "依据CAN下载协议";
CM_ SG_ 2149089125 P2D_BUCK_PHY_TX_Byte3_37 "依据CAN下载协议";
CM_ SG_ 2149089125 P2D_BUCK_PHY_TX_Byte4_37 "依据CAN下载协议";
CM_ SG_ 2149089125 P2D_BUCK_PHY_TX_Byte5_37 "依据CAN下载协议";
CM_ SG_ 2149089125 P2D_BUCK_PHY_TX_Byte6_37 "依据CAN下载协议";
CM_ SG_ 2149089125 P2D_BUCK_PHY_TX_Byte7_37 "依据CAN下载协议";
CM_ SG_ 2149089125 P2D_BUCK_PHY_TX_Byte8_37 "依据CAN下载协议";
CM_ SG_ 2149089126 P2D_BUCK_PHY_TX_Byte1_38 "依据CAN下载协议";
CM_ SG_ 2149089126 P2D_BUCK_PHY_TX_Byte2_38 "依据CAN下载协议";
CM_ SG_ 2149089126 P2D_BUCK_PHY_TX_Byte3_38 "依据CAN下载协议";
CM_ SG_ 2149089126 P2D_BUCK_PHY_TX_Byte4_38 "依据CAN下载协议";
CM_ SG_ 2149089126 P2D_BUCK_PHY_TX_Byte5_38 "依据CAN下载协议";
CM_ SG_ 2149089126 P2D_BUCK_PHY_TX_Byte6_38 "依据CAN下载协议";
CM_ SG_ 2149089126 P2D_BUCK_PHY_TX_Byte7_38 "依据CAN下载协议";
CM_ SG_ 2149089126 P2D_BUCK_PHY_TX_Byte8_38 "依据CAN下载协议";
CM_ SG_ 2149089127 P2D_BUCK_PHY_TX_Byte1_39 "依据CAN下载协议";
CM_ SG_ 2149089127 P2D_BUCK_PHY_TX_Byte2_39 "依据CAN下载协议";
CM_ SG_ 2149089127 P2D_BUCK_PHY_TX_Byte3_39 "依据CAN下载协议";
CM_ SG_ 2149089127 P2D_BUCK_PHY_TX_Byte4_39 "依据CAN下载协议";
CM_ SG_ 2149089127 P2D_BUCK_PHY_TX_Byte5_39 "依据CAN下载协议";
CM_ SG_ 2149089127 P2D_BUCK_PHY_TX_Byte6_39 "依据CAN下载协议";
CM_ SG_ 2149089127 P2D_BUCK_PHY_TX_Byte7_39 "依据CAN下载协议";
CM_ SG_ 2149089127 P2D_BUCK_PHY_TX_Byte8_39 "依据CAN下载协议";
CM_ SG_ 2149089128 P2D_BUCK_PHY_TX_Byte1_40 "依据CAN下载协议";
CM_ SG_ 2149089128 P2D_BUCK_PHY_TX_Byte2_40 "依据CAN下载协议";
CM_ SG_ 2149089128 P2D_BUCK_PHY_TX_Byte3_40 "依据CAN下载协议";
CM_ SG_ 2149089128 P2D_BUCK_PHY_TX_Byte4_40 "依据CAN下载协议";
CM_ SG_ 2149089128 P2D_BUCK_PHY_TX_Byte5_40 "依据CAN下载协议";
CM_ SG_ 2149089128 P2D_BUCK_PHY_TX_Byte6_40 "依据CAN下载协议";
CM_ SG_ 2149089128 P2D_BUCK_PHY_TX_Byte7_40 "依据CAN下载协议";
CM_ SG_ 2149089128 P2D_BUCK_PHY_TX_Byte8_40 "依据CAN下载协议";
CM_ SG_ 2149089129 P2D_BUCK_PHY_TX_Byte1_41 "依据CAN下载协议";
CM_ SG_ 2149089129 P2D_BUCK_PHY_TX_Byte2_41 "依据CAN下载协议";
CM_ SG_ 2149089129 P2D_BUCK_PHY_TX_Byte3_41 "依据CAN下载协议";
CM_ SG_ 2149089129 P2D_BUCK_PHY_TX_Byte4_41 "依据CAN下载协议";
CM_ SG_ 2149089129 P2D_BUCK_PHY_TX_Byte5_41 "依据CAN下载协议";
CM_ SG_ 2149089129 P2D_BUCK_PHY_TX_Byte6_41 "依据CAN下载协议";
CM_ SG_ 2149089129 P2D_BUCK_PHY_TX_Byte7_41 "依据CAN下载协议";
CM_ SG_ 2149089129 P2D_BUCK_PHY_TX_Byte8_41 "依据CAN下载协议";
CM_ SG_ 2149089130 P2D_BUCK_PHY_TX_Byte1_42 "依据CAN下载协议";
CM_ SG_ 2149089130 P2D_BUCK_PHY_TX_Byte2_42 "依据CAN下载协议";
CM_ SG_ 2149089130 P2D_BUCK_PHY_TX_Byte3_42 "依据CAN下载协议";
CM_ SG_ 2149089130 P2D_BUCK_PHY_TX_Byte4_42 "依据CAN下载协议";
CM_ SG_ 2149089130 P2D_BUCK_PHY_TX_Byte5_42 "依据CAN下载协议";
CM_ SG_ 2149089130 P2D_BUCK_PHY_TX_Byte6_42 "依据CAN下载协议";
CM_ SG_ 2149089130 P2D_BUCK_PHY_TX_Byte7_42 "依据CAN下载协议";
CM_ SG_ 2149089130 P2D_BUCK_PHY_TX_Byte8_42 "依据CAN下载协议";
CM_ SG_ 2149089131 P2D_BUCK_PHY_TX_Byte1_43 "依据CAN下载协议";
CM_ SG_ 2149089131 P2D_BUCK_PHY_TX_Byte2_43 "依据CAN下载协议";
CM_ SG_ 2149089131 P2D_BUCK_PHY_TX_Byte3_43 "依据CAN下载协议";
CM_ SG_ 2149089131 P2D_BUCK_PHY_TX_Byte4_43 "依据CAN下载协议";
CM_ SG_ 2149089131 P2D_BUCK_PHY_TX_Byte5_43 "依据CAN下载协议";
CM_ SG_ 2149089131 P2D_BUCK_PHY_TX_Byte6_43 "依据CAN下载协议";
CM_ SG_ 2149089131 P2D_BUCK_PHY_TX_Byte7_43 "依据CAN下载协议";
CM_ SG_ 2149089131 P2D_BUCK_PHY_TX_Byte8_43 "依据CAN下载协议";
CM_ SG_ 2149089132 P2D_BUCK_PHY_TX_Byte1_44 "依据CAN下载协议";
CM_ SG_ 2149089132 P2D_BUCK_PHY_TX_Byte2_44 "依据CAN下载协议";
CM_ SG_ 2149089132 P2D_BUCK_PHY_TX_Byte3_44 "依据CAN下载协议";
CM_ SG_ 2149089132 P2D_BUCK_PHY_TX_Byte4_44 "依据CAN下载协议";
CM_ SG_ 2149089132 P2D_BUCK_PHY_TX_Byte5_44 "依据CAN下载协议";
CM_ SG_ 2149089132 P2D_BUCK_PHY_TX_Byte6_44 "依据CAN下载协议";
CM_ SG_ 2149089132 P2D_BUCK_PHY_TX_Byte7_44 "依据CAN下载协议";
CM_ SG_ 2149089132 P2D_BUCK_PHY_TX_Byte8_44 "依据CAN下载协议";
CM_ SG_ 2149089133 P2D_BUCK_PHY_TX_Byte1_45 "依据CAN下载协议";
CM_ SG_ 2149089133 P2D_BUCK_PHY_TX_Byte2_45 "依据CAN下载协议";
CM_ SG_ 2149089133 P2D_BUCK_PHY_TX_Byte3_45 "依据CAN下载协议";
CM_ SG_ 2149089133 P2D_BUCK_PHY_TX_Byte4_45 "依据CAN下载协议";
CM_ SG_ 2149089133 P2D_BUCK_PHY_TX_Byte5_45 "依据CAN下载协议";
CM_ SG_ 2149089133 P2D_BUCK_PHY_TX_Byte6_45 "依据CAN下载协议";
CM_ SG_ 2149089133 P2D_BUCK_PHY_TX_Byte7_45 "依据CAN下载协议";
CM_ SG_ 2149089133 P2D_BUCK_PHY_TX_Byte8_45 "依据CAN下载协议";
CM_ SG_ 2149089134 P2D_BUCK_PHY_TX_Byte1_46 "依据CAN下载协议";
CM_ SG_ 2149089134 P2D_BUCK_PHY_TX_Byte2_46 "依据CAN下载协议";
CM_ SG_ 2149089134 P2D_BUCK_PHY_TX_Byte3_46 "依据CAN下载协议";
CM_ SG_ 2149089134 P2D_BUCK_PHY_TX_Byte4_46 "依据CAN下载协议";
CM_ SG_ 2149089134 P2D_BUCK_PHY_TX_Byte5_46 "依据CAN下载协议";
CM_ SG_ 2149089134 P2D_BUCK_PHY_TX_Byte6_46 "依据CAN下载协议";
CM_ SG_ 2149089134 P2D_BUCK_PHY_TX_Byte7_46 "依据CAN下载协议";
CM_ SG_ 2149089134 P2D_BUCK_PHY_TX_Byte8_46 "依据CAN下载协议";
CM_ SG_ 2149089135 P2D_BUCK_PHY_TX_Byte1_47 "依据CAN下载协议";
CM_ SG_ 2149089135 P2D_BUCK_PHY_TX_Byte2_47 "依据CAN下载协议";
CM_ SG_ 2149089135 P2D_BUCK_PHY_TX_Byte3_47 "依据CAN下载协议";
CM_ SG_ 2149089135 P2D_BUCK_PHY_TX_Byte4_47 "依据CAN下载协议";
CM_ SG_ 2149089135 P2D_BUCK_PHY_TX_Byte5_47 "依据CAN下载协议";
CM_ SG_ 2149089135 P2D_BUCK_PHY_TX_Byte6_47 "依据CAN下载协议";
CM_ SG_ 2149089135 P2D_BUCK_PHY_TX_Byte7_47 "依据CAN下载协议";
CM_ SG_ 2149089135 P2D_BUCK_PHY_TX_Byte8_47 "依据CAN下载协议";
CM_ SG_ 2149089136 P2D_BUCK_PHY_TX_Byte1_48 "依据CAN下载协议";
CM_ SG_ 2149089136 P2D_BUCK_PHY_TX_Byte2_48 "依据CAN下载协议";
CM_ SG_ 2149089136 P2D_BUCK_PHY_TX_Byte3_48 "依据CAN下载协议";
CM_ SG_ 2149089136 P2D_BUCK_PHY_TX_Byte4_48 "依据CAN下载协议";
CM_ SG_ 2149089136 P2D_BUCK_PHY_TX_Byte5_48 "依据CAN下载协议";
CM_ SG_ 2149089136 P2D_BUCK_PHY_TX_Byte6_48 "依据CAN下载协议";
CM_ SG_ 2149089136 P2D_BUCK_PHY_TX_Byte7_48 "依据CAN下载协议";
CM_ SG_ 2149089136 P2D_BUCK_PHY_TX_Byte8_48 "依据CAN下载协议";
CM_ SG_ 2149089137 P2D_BUCK_PHY_TX_Byte1_49 "依据CAN下载协议";
CM_ SG_ 2149089137 P2D_BUCK_PHY_TX_Byte2_49 "依据CAN下载协议";
CM_ SG_ 2149089137 P2D_BUCK_PHY_TX_Byte3_49 "依据CAN下载协议";
CM_ SG_ 2149089137 P2D_BUCK_PHY_TX_Byte4_49 "依据CAN下载协议";
CM_ SG_ 2149089137 P2D_BUCK_PHY_TX_Byte5_49 "依据CAN下载协议";
CM_ SG_ 2149089137 P2D_BUCK_PHY_TX_Byte6_49 "依据CAN下载协议";
CM_ SG_ 2149089137 P2D_BUCK_PHY_TX_Byte7_49 "依据CAN下载协议";
CM_ SG_ 2149089137 P2D_BUCK_PHY_TX_Byte8_49 "依据CAN下载协议";
CM_ SG_ 2149089138 P2D_BUCK_PHY_TX_Byte1_50 "依据CAN下载协议";
CM_ SG_ 2149089138 P2D_BUCK_PHY_TX_Byte2_50 "依据CAN下载协议";
CM_ SG_ 2149089138 P2D_BUCK_PHY_TX_Byte3_50 "依据CAN下载协议";
CM_ SG_ 2149089138 P2D_BUCK_PHY_TX_Byte4_50 "依据CAN下载协议";
CM_ SG_ 2149089138 P2D_BUCK_PHY_TX_Byte5_50 "依据CAN下载协议";
CM_ SG_ 2149089138 P2D_BUCK_PHY_TX_Byte6_50 "依据CAN下载协议";
CM_ SG_ 2149089138 P2D_BUCK_PHY_TX_Byte7_50 "依据CAN下载协议";
CM_ SG_ 2149089138 P2D_BUCK_PHY_TX_Byte8_50 "依据CAN下载协议";
CM_ SG_ 2149089139 P2D_BUCK_PHY_TX_Byte1_51 "依据CAN下载协议";
CM_ SG_ 2149089139 P2D_BUCK_PHY_TX_Byte2_51 "依据CAN下载协议";
CM_ SG_ 2149089139 P2D_BUCK_PHY_TX_Byte3_51 "依据CAN下载协议";
CM_ SG_ 2149089139 P2D_BUCK_PHY_TX_Byte4_51 "依据CAN下载协议";
CM_ SG_ 2149089139 P2D_BUCK_PHY_TX_Byte5_51 "依据CAN下载协议";
CM_ SG_ 2149089139 P2D_BUCK_PHY_TX_Byte6_51 "依据CAN下载协议";
CM_ SG_ 2149089139 P2D_BUCK_PHY_TX_Byte7_51 "依据CAN下载协议";
CM_ SG_ 2149089139 P2D_BUCK_PHY_TX_Byte8_51 "依据CAN下载协议";
CM_ SG_ 2149089140 P2D_BUCK_PHY_TX_Byte1_52 "依据CAN下载协议";
CM_ SG_ 2149089140 P2D_BUCK_PHY_TX_Byte2_52 "依据CAN下载协议";
CM_ SG_ 2149089140 P2D_BUCK_PHY_TX_Byte3_52 "依据CAN下载协议";
CM_ SG_ 2149089140 P2D_BUCK_PHY_TX_Byte4_52 "依据CAN下载协议";
CM_ SG_ 2149089140 P2D_BUCK_PHY_TX_Byte5_52 "依据CAN下载协议";
CM_ SG_ 2149089140 P2D_BUCK_PHY_TX_Byte6_52 "依据CAN下载协议";
CM_ SG_ 2149089140 P2D_BUCK_PHY_TX_Byte7_52 "依据CAN下载协议";
CM_ SG_ 2149089140 P2D_BUCK_PHY_TX_Byte8_52 "依据CAN下载协议";
CM_ SG_ 2149089141 P2D_BUCK_PHY_TX_Byte1_53 "依据CAN下载协议";
CM_ SG_ 2149089141 P2D_BUCK_PHY_TX_Byte2_53 "依据CAN下载协议";
CM_ SG_ 2149089141 P2D_BUCK_PHY_TX_Byte3_53 "依据CAN下载协议";
CM_ SG_ 2149089141 P2D_BUCK_PHY_TX_Byte4_53 "依据CAN下载协议";
CM_ SG_ 2149089141 P2D_BUCK_PHY_TX_Byte5_53 "依据CAN下载协议";
CM_ SG_ 2149089141 P2D_BUCK_PHY_TX_Byte6_53 "依据CAN下载协议";
CM_ SG_ 2149089141 P2D_BUCK_PHY_TX_Byte7_53 "依据CAN下载协议";
CM_ SG_ 2149089141 P2D_BUCK_PHY_TX_Byte8_53 "依据CAN下载协议";
CM_ SG_ 2149089142 P2D_BUCK_PHY_TX_Byte1_54 "依据CAN下载协议";
CM_ SG_ 2149089142 P2D_BUCK_PHY_TX_Byte2_54 "依据CAN下载协议";
CM_ SG_ 2149089142 P2D_BUCK_PHY_TX_Byte3_54 "依据CAN下载协议";
CM_ SG_ 2149089142 P2D_BUCK_PHY_TX_Byte4_54 "依据CAN下载协议";
CM_ SG_ 2149089142 P2D_BUCK_PHY_TX_Byte5_54 "依据CAN下载协议";
CM_ SG_ 2149089142 P2D_BUCK_PHY_TX_Byte6_54 "依据CAN下载协议";
CM_ SG_ 2149089142 P2D_BUCK_PHY_TX_Byte7_54 "依据CAN下载协议";
CM_ SG_ 2149089142 P2D_BUCK_PHY_TX_Byte8_54 "依据CAN下载协议";
CM_ SG_ 2149089143 P2D_BUCK_PHY_TX_Byte1_55 "依据CAN下载协议";
CM_ SG_ 2149089143 P2D_BUCK_PHY_TX_Byte2_55 "依据CAN下载协议";
CM_ SG_ 2149089143 P2D_BUCK_PHY_TX_Byte3_55 "依据CAN下载协议";
CM_ SG_ 2149089143 P2D_BUCK_PHY_TX_Byte4_55 "依据CAN下载协议";
CM_ SG_ 2149089143 P2D_BUCK_PHY_TX_Byte5_55 "依据CAN下载协议";
CM_ SG_ 2149089143 P2D_BUCK_PHY_TX_Byte6_55 "依据CAN下载协议";
CM_ SG_ 2149089143 P2D_BUCK_PHY_TX_Byte7_55 "依据CAN下载协议";
CM_ SG_ 2149089143 P2D_BUCK_PHY_TX_Byte8_55 "依据CAN下载协议";
CM_ SG_ 2149089144 P2D_BUCK_PHY_TX_Byte1_56 "依据CAN下载协议";
CM_ SG_ 2149089144 P2D_BUCK_PHY_TX_Byte2_56 "依据CAN下载协议";
CM_ SG_ 2149089144 P2D_BUCK_PHY_TX_Byte3_56 "依据CAN下载协议";
CM_ SG_ 2149089144 P2D_BUCK_PHY_TX_Byte4_56 "依据CAN下载协议";
CM_ SG_ 2149089144 P2D_BUCK_PHY_TX_Byte5_56 "依据CAN下载协议";
CM_ SG_ 2149089144 P2D_BUCK_PHY_TX_Byte6_56 "依据CAN下载协议";
CM_ SG_ 2149089144 P2D_BUCK_PHY_TX_Byte7_56 "依据CAN下载协议";
CM_ SG_ 2149089144 P2D_BUCK_PHY_TX_Byte8_56 "依据CAN下载协议";
CM_ SG_ 2149089145 P2D_BUCK_PHY_TX_Byte1_57 "依据CAN下载协议";
CM_ SG_ 2149089145 P2D_BUCK_PHY_TX_Byte2_57 "依据CAN下载协议";
CM_ SG_ 2149089145 P2D_BUCK_PHY_TX_Byte3_57 "依据CAN下载协议";
CM_ SG_ 2149089145 P2D_BUCK_PHY_TX_Byte4_57 "依据CAN下载协议";
CM_ SG_ 2149089145 P2D_BUCK_PHY_TX_Byte5_57 "依据CAN下载协议";
CM_ SG_ 2149089145 P2D_BUCK_PHY_TX_Byte6_57 "依据CAN下载协议";
CM_ SG_ 2149089145 P2D_BUCK_PHY_TX_Byte7_57 "依据CAN下载协议";
CM_ SG_ 2149089145 P2D_BUCK_PHY_TX_Byte8_57 "依据CAN下载协议";
CM_ SG_ 2149089146 P2D_BUCK_PHY_TX_Byte1_58 "依据CAN下载协议";
CM_ SG_ 2149089146 P2D_BUCK_PHY_TX_Byte2_58 "依据CAN下载协议";
CM_ SG_ 2149089146 P2D_BUCK_PHY_TX_Byte3_58 "依据CAN下载协议";
CM_ SG_ 2149089146 P2D_BUCK_PHY_TX_Byte4_58 "依据CAN下载协议";
CM_ SG_ 2149089146 P2D_BUCK_PHY_TX_Byte5_58 "依据CAN下载协议";
CM_ SG_ 2149089146 P2D_BUCK_PHY_TX_Byte6_58 "依据CAN下载协议";
CM_ SG_ 2149089146 P2D_BUCK_PHY_TX_Byte7_58 "依据CAN下载协议";
CM_ SG_ 2149089146 P2D_BUCK_PHY_TX_Byte8_58 "依据CAN下载协议";
CM_ SG_ 2149089147 P2D_BUCK_PHY_TX_Byte1_59 "依据CAN下载协议";
CM_ SG_ 2149089147 P2D_BUCK_PHY_TX_Byte2_59 "依据CAN下载协议";
CM_ SG_ 2149089147 P2D_BUCK_PHY_TX_Byte3_59 "依据CAN下载协议";
CM_ SG_ 2149089147 P2D_BUCK_PHY_TX_Byte4_59 "依据CAN下载协议";
CM_ SG_ 2149089147 P2D_BUCK_PHY_TX_Byte5_59 "依据CAN下载协议";
CM_ SG_ 2149089147 P2D_BUCK_PHY_TX_Byte6_59 "依据CAN下载协议";
CM_ SG_ 2149089147 P2D_BUCK_PHY_TX_Byte7_59 "依据CAN下载协议";
CM_ SG_ 2149089147 P2D_BUCK_PHY_TX_Byte8_59 "依据CAN下载协议";
CM_ SG_ 2149089148 P2D_BUCK_PHY_TX_Byte1_60 "依据CAN下载协议";
CM_ SG_ 2149089148 P2D_BUCK_PHY_TX_Byte2_60 "依据CAN下载协议";
CM_ SG_ 2149089148 P2D_BUCK_PHY_TX_Byte3_60 "依据CAN下载协议";
CM_ SG_ 2149089148 P2D_BUCK_PHY_TX_Byte4_60 "依据CAN下载协议";
CM_ SG_ 2149089148 P2D_BUCK_PHY_TX_Byte5_60 "依据CAN下载协议";
CM_ SG_ 2149089148 P2D_BUCK_PHY_TX_Byte6_60 "依据CAN下载协议";
CM_ SG_ 2149089148 P2D_BUCK_PHY_TX_Byte7_60 "依据CAN下载协议";
CM_ SG_ 2149089148 P2D_BUCK_PHY_TX_Byte8_60 "依据CAN下载协议";
CM_ SG_ 2149089149 P2D_BUCK_PHY_TX_Byte1_61 "依据CAN下载协议";
CM_ SG_ 2149089149 P2D_BUCK_PHY_TX_Byte2_61 "依据CAN下载协议";
CM_ SG_ 2149089149 P2D_BUCK_PHY_TX_Byte3_61 "依据CAN下载协议";
CM_ SG_ 2149089149 P2D_BUCK_PHY_TX_Byte4_61 "依据CAN下载协议";
CM_ SG_ 2149089149 P2D_BUCK_PHY_TX_Byte5_61 "依据CAN下载协议";
CM_ SG_ 2149089149 P2D_BUCK_PHY_TX_Byte6_61 "依据CAN下载协议";
CM_ SG_ 2149089149 P2D_BUCK_PHY_TX_Byte7_61 "依据CAN下载协议";
CM_ SG_ 2149089149 P2D_BUCK_PHY_TX_Byte8_61 "依据CAN下载协议";
CM_ SG_ 2149089150 P2D_BUCK_PHY_TX_Byte1_62 "依据CAN下载协议";
CM_ SG_ 2149089150 P2D_BUCK_PHY_TX_Byte2_62 "依据CAN下载协议";
CM_ SG_ 2149089150 P2D_BUCK_PHY_TX_Byte3_62 "依据CAN下载协议";
CM_ SG_ 2149089150 P2D_BUCK_PHY_TX_Byte4_62 "依据CAN下载协议";
CM_ SG_ 2149089150 P2D_BUCK_PHY_TX_Byte5_62 "依据CAN下载协议";
CM_ SG_ 2149089150 P2D_BUCK_PHY_TX_Byte6_62 "依据CAN下载协议";
CM_ SG_ 2149089150 P2D_BUCK_PHY_TX_Byte7_62 "依据CAN下载协议";
CM_ SG_ 2149089150 P2D_BUCK_PHY_TX_Byte8_62 "依据CAN下载协议";
CM_ SG_ 2149089151 P2D_BUCK_PHY_TX_Byte1_63 "依据CAN下载协议";
CM_ SG_ 2149089151 P2D_BUCK_PHY_TX_Byte2_63 "依据CAN下载协议";
CM_ SG_ 2149089151 P2D_BUCK_PHY_TX_Byte3_63 "依据CAN下载协议";
CM_ SG_ 2149089151 P2D_BUCK_PHY_TX_Byte4_63 "依据CAN下载协议";
CM_ SG_ 2149089151 P2D_BUCK_PHY_TX_Byte5_63 "依据CAN下载协议";
CM_ SG_ 2149089151 P2D_BUCK_PHY_TX_Byte6_63 "依据CAN下载协议";
CM_ SG_ 2149089151 P2D_BUCK_PHY_TX_Byte7_63 "依据CAN下载协议";
CM_ SG_ 2149089151 P2D_BUCK_PHY_TX_Byte8_63 "依据CAN下载协议";
CM_ SG_ 2149154625 P2D_PrgInfo_Data0 "发送的待下载总页数信息报文字节0";
CM_ SG_ 2149154625 P2D_PrgInfo_Data1 "发送的待下载总页数信息报文字节1";
CM_ SG_ 2149154625 P2D_PrgInfo_Data2 "发送的待下载总页数信息报文字节2";
CM_ SG_ 2149154625 P2D_PrgInfo_Data3 "发送的待下载总页数信息报文字节3";
CM_ SG_ 2149154625 P2D_PrgInfo_Data4 "发送的待下载总页数信息报文字节4";
CM_ SG_ 2149154625 P2D_PrgInfo_Data5 "发送的待下载总页数信息报文字节5";
CM_ SG_ 2149154625 P2D_PrgInfo_Data6 "发送的待下载总页数信息报文字节6";
CM_ SG_ 2149154625 P2D_PrgInfo_Data7 "发送的待下载总页数信息报文字节7";
CM_ SG_ 2149154626 P2D_PrgInfo_Data0 "发送的待下载总页数信息报文字节0";
CM_ SG_ 2149154626 P2D_PrgInfo_Data1 "发送的待下载总页数信息报文字节1";
CM_ SG_ 2149154626 P2D_PrgInfo_Data2 "发送的待下载总页数信息报文字节2";
CM_ SG_ 2149154626 P2D_PrgInfo_Data3 "发送的待下载总页数信息报文字节3";
CM_ SG_ 2149154626 P2D_PrgInfo_Data4 "发送的待下载总页数信息报文字节4";
CM_ SG_ 2149154626 P2D_PrgInfo_Data5 "发送的待下载总页数信息报文字节5";
CM_ SG_ 2149154626 P2D_PrgInfo_Data6 "发送的待下载总页数信息报文字节6";
CM_ SG_ 2149154626 P2D_PrgInfo_Data7 "发送的待下载总页数信息报文字节7";
CM_ SG_ 2149154627 P2D_PrgInfo_Data0 "发送的待下载总页数信息报文字节0";
CM_ SG_ 2149154627 P2D_PrgInfo_Data1 "发送的待下载总页数信息报文字节1";
CM_ SG_ 2149154627 P2D_PrgInfo_Data2 "发送的待下载总页数信息报文字节2";
CM_ SG_ 2149154627 P2D_PrgInfo_Data3 "发送的待下载总页数信息报文字节3";
CM_ SG_ 2149154627 P2D_PrgInfo_Data4 "发送的待下载总页数信息报文字节4";
CM_ SG_ 2149154627 P2D_PrgInfo_Data5 "发送的待下载总页数信息报文字节5";
CM_ SG_ 2149154627 P2D_PrgInfo_Data6 "发送的待下载总页数信息报文字节6";
CM_ SG_ 2149154627 P2D_PrgInfo_Data7 "发送的待下载总页数信息报文字节7";
CM_ SG_ 2149154628 P2D_PrgInfo_Data0 "发送的待下载总页数信息报文字节0";
CM_ SG_ 2149154628 P2D_PrgInfo_Data1 "发送的待下载总页数信息报文字节1";
CM_ SG_ 2149154628 P2D_PrgInfo_Data2 "发送的待下载总页数信息报文字节2";
CM_ SG_ 2149154628 P2D_PrgInfo_Data3 "发送的待下载总页数信息报文字节3";
CM_ SG_ 2149154628 P2D_PrgInfo_Data4 "发送的待下载总页数信息报文字节4";
CM_ SG_ 2149154628 P2D_PrgInfo_Data5 "发送的待下载总页数信息报文字节5";
CM_ SG_ 2149154628 P2D_PrgInfo_Data6 "发送的待下载总页数信息报文字节6";
CM_ SG_ 2149154628 P2D_PrgInfo_Data7 "发送的待下载总页数信息报文字节7";
CM_ SG_ 2149154629 P2D_PrgInfo_Data0 "发送的待下载总页数信息报文字节0";
CM_ SG_ 2149154629 P2D_PrgInfo_Data1 "发送的待下载总页数信息报文字节1";
CM_ SG_ 2149154629 P2D_PrgInfo_Data2 "发送的待下载总页数信息报文字节2";
CM_ SG_ 2149154629 P2D_PrgInfo_Data3 "发送的待下载总页数信息报文字节3";
CM_ SG_ 2149154629 P2D_PrgInfo_Data4 "发送的待下载总页数信息报文字节4";
CM_ SG_ 2149154629 P2D_PrgInfo_Data5 "发送的待下载总页数信息报文字节5";
CM_ SG_ 2149154629 P2D_PrgInfo_Data6 "发送的待下载总页数信息报文字节6";
CM_ SG_ 2149154629 P2D_PrgInfo_Data7 "发送的待下载总页数信息报文字节7";
CM_ SG_ 2149154630 P2D_PrgInfo_Data0 "发送的待下载总页数信息报文字节0";
CM_ SG_ 2149154630 P2D_PrgInfo_Data1 "发送的待下载总页数信息报文字节1";
CM_ SG_ 2149154630 P2D_PrgInfo_Data2 "发送的待下载总页数信息报文字节2";
CM_ SG_ 2149154630 P2D_PrgInfo_Data3 "发送的待下载总页数信息报文字节3";
CM_ SG_ 2149154630 P2D_PrgInfo_Data4 "发送的待下载总页数信息报文字节4";
CM_ SG_ 2149154630 P2D_PrgInfo_Data5 "发送的待下载总页数信息报文字节5";
CM_ SG_ 2149154630 P2D_PrgInfo_Data6 "发送的待下载总页数信息报文字节6";
CM_ SG_ 2149154630 P2D_PrgInfo_Data7 "发送的待下载总页数信息报文字节7";
CM_ SG_ 2149154631 P2D_PrgInfo_Data0 "发送的待下载总页数信息报文字节0";
CM_ SG_ 2149154631 P2D_PrgInfo_Data1 "发送的待下载总页数信息报文字节1";
CM_ SG_ 2149154631 P2D_PrgInfo_Data2 "发送的待下载总页数信息报文字节2";
CM_ SG_ 2149154631 P2D_PrgInfo_Data3 "发送的待下载总页数信息报文字节3";
CM_ SG_ 2149154631 P2D_PrgInfo_Data4 "发送的待下载总页数信息报文字节4";
CM_ SG_ 2149154631 P2D_PrgInfo_Data5 "发送的待下载总页数信息报文字节5";
CM_ SG_ 2149154631 P2D_PrgInfo_Data6 "发送的待下载总页数信息报文字节6";
CM_ SG_ 2149154631 P2D_PrgInfo_Data7 "发送的待下载总页数信息报文字节7";
CM_ SG_ 2149154632 P2D_PrgInfo_Data0 "发送的待下载总页数信息报文字节0";
CM_ SG_ 2149154632 P2D_PrgInfo_Data1 "发送的待下载总页数信息报文字节1";
CM_ SG_ 2149154632 P2D_PrgInfo_Data2 "发送的待下载总页数信息报文字节2";
CM_ SG_ 2149154632 P2D_PrgInfo_Data3 "发送的待下载总页数信息报文字节3";
CM_ SG_ 2149154632 P2D_PrgInfo_Data4 "发送的待下载总页数信息报文字节4";
CM_ SG_ 2149154632 P2D_PrgInfo_Data5 "发送的待下载总页数信息报文字节5";
CM_ SG_ 2149154632 P2D_PrgInfo_Data6 "发送的待下载总页数信息报文字节6";
CM_ SG_ 2149154632 P2D_PrgInfo_Data7 "发送的待下载总页数信息报文字节7";
CM_ SG_ 2149154633 P2D_PrgInfo_Data0 "发送的待下载总页数信息报文字节0";
CM_ SG_ 2149154633 P2D_PrgInfo_Data1 "发送的待下载总页数信息报文字节1";
CM_ SG_ 2149154633 P2D_PrgInfo_Data2 "发送的待下载总页数信息报文字节2";
CM_ SG_ 2149154633 P2D_PrgInfo_Data3 "发送的待下载总页数信息报文字节3";
CM_ SG_ 2149154633 P2D_PrgInfo_Data4 "发送的待下载总页数信息报文字节4";
CM_ SG_ 2149154633 P2D_PrgInfo_Data5 "发送的待下载总页数信息报文字节5";
CM_ SG_ 2149154633 P2D_PrgInfo_Data6 "发送的待下载总页数信息报文字节6";
CM_ SG_ 2149154633 P2D_PrgInfo_Data7 "发送的待下载总页数信息报文字节7";
CM_ SG_ 2149154634 P2D_PrgInfo_Data0 "发送的待下载总页数信息报文字节0";
CM_ SG_ 2149154634 P2D_PrgInfo_Data1 "发送的待下载总页数信息报文字节1";
CM_ SG_ 2149154634 P2D_PrgInfo_Data2 "发送的待下载总页数信息报文字节2";
CM_ SG_ 2149154634 P2D_PrgInfo_Data3 "发送的待下载总页数信息报文字节3";
CM_ SG_ 2149154634 P2D_PrgInfo_Data4 "发送的待下载总页数信息报文字节4";
CM_ SG_ 2149154634 P2D_PrgInfo_Data5 "发送的待下载总页数信息报文字节5";
CM_ SG_ 2149154634 P2D_PrgInfo_Data6 "发送的待下载总页数信息报文字节6";
CM_ SG_ 2149154634 P2D_PrgInfo_Data7 "发送的待下载总页数信息报文字节7";
CM_ SG_ 2149154635 P2D_PrgInfo_Data0 "发送的待下载总页数信息报文字节0";
CM_ SG_ 2149154635 P2D_PrgInfo_Data1 "发送的待下载总页数信息报文字节1";
CM_ SG_ 2149154635 P2D_PrgInfo_Data2 "发送的待下载总页数信息报文字节2";
CM_ SG_ 2149154635 P2D_PrgInfo_Data3 "发送的待下载总页数信息报文字节3";
CM_ SG_ 2149154635 P2D_PrgInfo_Data4 "发送的待下载总页数信息报文字节4";
CM_ SG_ 2149154635 P2D_PrgInfo_Data5 "发送的待下载总页数信息报文字节5";
CM_ SG_ 2149154635 P2D_PrgInfo_Data6 "发送的待下载总页数信息报文字节6";
CM_ SG_ 2149154635 P2D_PrgInfo_Data7 "发送的待下载总页数信息报文字节7";
CM_ SG_ 2149154636 P2D_PrgInfo_Data0 "发送的待下载总页数信息报文字节0";
CM_ SG_ 2149154636 P2D_PrgInfo_Data1 "发送的待下载总页数信息报文字节1";
CM_ SG_ 2149154636 P2D_PrgInfo_Data2 "发送的待下载总页数信息报文字节2";
CM_ SG_ 2149154636 P2D_PrgInfo_Data3 "发送的待下载总页数信息报文字节3";
CM_ SG_ 2149154636 P2D_PrgInfo_Data4 "发送的待下载总页数信息报文字节4";
CM_ SG_ 2149154636 P2D_PrgInfo_Data5 "发送的待下载总页数信息报文字节5";
CM_ SG_ 2149154636 P2D_PrgInfo_Data6 "发送的待下载总页数信息报文字节6";
CM_ SG_ 2149154636 P2D_PrgInfo_Data7 "发送的待下载总页数信息报文字节7";
CM_ SG_ 2149154637 P2D_PrgInfo_Data0 "发送的待下载总页数信息报文字节0";
CM_ SG_ 2149154637 P2D_PrgInfo_Data1 "发送的待下载总页数信息报文字节1";
CM_ SG_ 2149154637 P2D_PrgInfo_Data2 "发送的待下载总页数信息报文字节2";
CM_ SG_ 2149154637 P2D_PrgInfo_Data3 "发送的待下载总页数信息报文字节3";
CM_ SG_ 2149154637 P2D_PrgInfo_Data4 "发送的待下载总页数信息报文字节4";
CM_ SG_ 2149154637 P2D_PrgInfo_Data5 "发送的待下载总页数信息报文字节5";
CM_ SG_ 2149154637 P2D_PrgInfo_Data6 "发送的待下载总页数信息报文字节6";
CM_ SG_ 2149154637 P2D_PrgInfo_Data7 "发送的待下载总页数信息报文字节7";
CM_ SG_ 2149154638 P2D_PrgInfo_Data0 "发送的待下载总页数信息报文字节0";
CM_ SG_ 2149154638 P2D_PrgInfo_Data1 "发送的待下载总页数信息报文字节1";
CM_ SG_ 2149154638 P2D_PrgInfo_Data2 "发送的待下载总页数信息报文字节2";
CM_ SG_ 2149154638 P2D_PrgInfo_Data3 "发送的待下载总页数信息报文字节3";
CM_ SG_ 2149154638 P2D_PrgInfo_Data4 "发送的待下载总页数信息报文字节4";
CM_ SG_ 2149154638 P2D_PrgInfo_Data5 "发送的待下载总页数信息报文字节5";
CM_ SG_ 2149154638 P2D_PrgInfo_Data6 "发送的待下载总页数信息报文字节6";
CM_ SG_ 2149154638 P2D_PrgInfo_Data7 "发送的待下载总页数信息报文字节7";
CM_ SG_ 2149154639 P2D_PrgInfo_Data0 "发送的待下载总页数信息报文字节0";
CM_ SG_ 2149154639 P2D_PrgInfo_Data1 "发送的待下载总页数信息报文字节1";
CM_ SG_ 2149154639 P2D_PrgInfo_Data2 "发送的待下载总页数信息报文字节2";
CM_ SG_ 2149154639 P2D_PrgInfo_Data3 "发送的待下载总页数信息报文字节3";
CM_ SG_ 2149154639 P2D_PrgInfo_Data4 "发送的待下载总页数信息报文字节4";
CM_ SG_ 2149154639 P2D_PrgInfo_Data5 "发送的待下载总页数信息报文字节5";
CM_ SG_ 2149154639 P2D_PrgInfo_Data6 "发送的待下载总页数信息报文字节6";
CM_ SG_ 2149154639 P2D_PrgInfo_Data7 "发送的待下载总页数信息报文字节7";
CM_ SG_ 2149154640 P2D_PrgInfo_Data0 "发送的待下载总页数信息报文字节0";
CM_ SG_ 2149154640 P2D_PrgInfo_Data1 "发送的待下载总页数信息报文字节1";
CM_ SG_ 2149154640 P2D_PrgInfo_Data2 "发送的待下载总页数信息报文字节2";
CM_ SG_ 2149154640 P2D_PrgInfo_Data3 "发送的待下载总页数信息报文字节3";
CM_ SG_ 2149154640 P2D_PrgInfo_Data4 "发送的待下载总页数信息报文字节4";
CM_ SG_ 2149154640 P2D_PrgInfo_Data5 "发送的待下载总页数信息报文字节5";
CM_ SG_ 2149154640 P2D_PrgInfo_Data6 "发送的待下载总页数信息报文字节6";
CM_ SG_ 2149154640 P2D_PrgInfo_Data7 "发送的待下载总页数信息报文字节7";
CM_ SG_ 2149154641 P2D_PrgInfo_Data0 "发送的待下载总页数信息报文字节0";
CM_ SG_ 2149154641 P2D_PrgInfo_Data1 "发送的待下载总页数信息报文字节1";
CM_ SG_ 2149154641 P2D_PrgInfo_Data2 "发送的待下载总页数信息报文字节2";
CM_ SG_ 2149154641 P2D_PrgInfo_Data3 "发送的待下载总页数信息报文字节3";
CM_ SG_ 2149154641 P2D_PrgInfo_Data4 "发送的待下载总页数信息报文字节4";
CM_ SG_ 2149154641 P2D_PrgInfo_Data5 "发送的待下载总页数信息报文字节5";
CM_ SG_ 2149154641 P2D_PrgInfo_Data6 "发送的待下载总页数信息报文字节6";
CM_ SG_ 2149154641 P2D_PrgInfo_Data7 "发送的待下载总页数信息报文字节7";
CM_ SG_ 2149154642 P2D_PrgInfo_Data0 "发送的待下载总页数信息报文字节0";
CM_ SG_ 2149154642 P2D_PrgInfo_Data1 "发送的待下载总页数信息报文字节1";
CM_ SG_ 2149154642 P2D_PrgInfo_Data2 "发送的待下载总页数信息报文字节2";
CM_ SG_ 2149154642 P2D_PrgInfo_Data3 "发送的待下载总页数信息报文字节3";
CM_ SG_ 2149154642 P2D_PrgInfo_Data4 "发送的待下载总页数信息报文字节4";
CM_ SG_ 2149154642 P2D_PrgInfo_Data5 "发送的待下载总页数信息报文字节5";
CM_ SG_ 2149154642 P2D_PrgInfo_Data6 "发送的待下载总页数信息报文字节6";
CM_ SG_ 2149154642 P2D_PrgInfo_Data7 "发送的待下载总页数信息报文字节7";
CM_ SG_ 2149154643 P2D_PrgInfo_Data0 "发送的待下载总页数信息报文字节0";
CM_ SG_ 2149154643 P2D_PrgInfo_Data1 "发送的待下载总页数信息报文字节1";
CM_ SG_ 2149154643 P2D_PrgInfo_Data2 "发送的待下载总页数信息报文字节2";
CM_ SG_ 2149154643 P2D_PrgInfo_Data3 "发送的待下载总页数信息报文字节3";
CM_ SG_ 2149154643 P2D_PrgInfo_Data4 "发送的待下载总页数信息报文字节4";
CM_ SG_ 2149154643 P2D_PrgInfo_Data5 "发送的待下载总页数信息报文字节5";
CM_ SG_ 2149154643 P2D_PrgInfo_Data6 "发送的待下载总页数信息报文字节6";
CM_ SG_ 2149154643 P2D_PrgInfo_Data7 "发送的待下载总页数信息报文字节7";
CM_ SG_ 2149154644 P2D_PrgInfo_Data0 "发送的待下载总页数信息报文字节0";
CM_ SG_ 2149154644 P2D_PrgInfo_Data1 "发送的待下载总页数信息报文字节1";
CM_ SG_ 2149154644 P2D_PrgInfo_Data2 "发送的待下载总页数信息报文字节2";
CM_ SG_ 2149154644 P2D_PrgInfo_Data3 "发送的待下载总页数信息报文字节3";
CM_ SG_ 2149154644 P2D_PrgInfo_Data4 "发送的待下载总页数信息报文字节4";
CM_ SG_ 2149154644 P2D_PrgInfo_Data5 "发送的待下载总页数信息报文字节5";
CM_ SG_ 2149154644 P2D_PrgInfo_Data6 "发送的待下载总页数信息报文字节6";
CM_ SG_ 2149154644 P2D_PrgInfo_Data7 "发送的待下载总页数信息报文字节7";
CM_ SG_ 2149154645 P2D_PrgInfo_Data0 "发送的待下载总页数信息报文字节0";
CM_ SG_ 2149154645 P2D_PrgInfo_Data1 "发送的待下载总页数信息报文字节1";
CM_ SG_ 2149154645 P2D_PrgInfo_Data2 "发送的待下载总页数信息报文字节2";
CM_ SG_ 2149154645 P2D_PrgInfo_Data3 "发送的待下载总页数信息报文字节3";
CM_ SG_ 2149154645 P2D_PrgInfo_Data4 "发送的待下载总页数信息报文字节4";
CM_ SG_ 2149154645 P2D_PrgInfo_Data5 "发送的待下载总页数信息报文字节5";
CM_ SG_ 2149154645 P2D_PrgInfo_Data6 "发送的待下载总页数信息报文字节6";
CM_ SG_ 2149154645 P2D_PrgInfo_Data7 "发送的待下载总页数信息报文字节7";
CM_ SG_ 2149154646 P2D_PrgInfo_Data0 "发送的待下载总页数信息报文字节0";
CM_ SG_ 2149154646 P2D_PrgInfo_Data1 "发送的待下载总页数信息报文字节1";
CM_ SG_ 2149154646 P2D_PrgInfo_Data2 "发送的待下载总页数信息报文字节2";
CM_ SG_ 2149154646 P2D_PrgInfo_Data3 "发送的待下载总页数信息报文字节3";
CM_ SG_ 2149154646 P2D_PrgInfo_Data4 "发送的待下载总页数信息报文字节4";
CM_ SG_ 2149154646 P2D_PrgInfo_Data5 "发送的待下载总页数信息报文字节5";
CM_ SG_ 2149154646 P2D_PrgInfo_Data6 "发送的待下载总页数信息报文字节6";
CM_ SG_ 2149154646 P2D_PrgInfo_Data7 "发送的待下载总页数信息报文字节7";
CM_ SG_ 2149154647 P2D_PrgInfo_Data0 "发送的待下载总页数信息报文字节0";
CM_ SG_ 2149154647 P2D_PrgInfo_Data1 "发送的待下载总页数信息报文字节1";
CM_ SG_ 2149154647 P2D_PrgInfo_Data2 "发送的待下载总页数信息报文字节2";
CM_ SG_ 2149154647 P2D_PrgInfo_Data3 "发送的待下载总页数信息报文字节3";
CM_ SG_ 2149154647 P2D_PrgInfo_Data4 "发送的待下载总页数信息报文字节4";
CM_ SG_ 2149154647 P2D_PrgInfo_Data5 "发送的待下载总页数信息报文字节5";
CM_ SG_ 2149154647 P2D_PrgInfo_Data6 "发送的待下载总页数信息报文字节6";
CM_ SG_ 2149154647 P2D_PrgInfo_Data7 "发送的待下载总页数信息报文字节7";
CM_ SG_ 2149154648 P2D_PrgInfo_Data0 "发送的待下载总页数信息报文字节0";
CM_ SG_ 2149154648 P2D_PrgInfo_Data1 "发送的待下载总页数信息报文字节1";
CM_ SG_ 2149154648 P2D_PrgInfo_Data2 "发送的待下载总页数信息报文字节2";
CM_ SG_ 2149154648 P2D_PrgInfo_Data3 "发送的待下载总页数信息报文字节3";
CM_ SG_ 2149154648 P2D_PrgInfo_Data4 "发送的待下载总页数信息报文字节4";
CM_ SG_ 2149154648 P2D_PrgInfo_Data5 "发送的待下载总页数信息报文字节5";
CM_ SG_ 2149154648 P2D_PrgInfo_Data6 "发送的待下载总页数信息报文字节6";
CM_ SG_ 2149154648 P2D_PrgInfo_Data7 "发送的待下载总页数信息报文字节7";
CM_ SG_ 2149154649 P2D_PrgInfo_Data0 "发送的待下载总页数信息报文字节0";
CM_ SG_ 2149154649 P2D_PrgInfo_Data1 "发送的待下载总页数信息报文字节1";
CM_ SG_ 2149154649 P2D_PrgInfo_Data2 "发送的待下载总页数信息报文字节2";
CM_ SG_ 2149154649 P2D_PrgInfo_Data3 "发送的待下载总页数信息报文字节3";
CM_ SG_ 2149154649 P2D_PrgInfo_Data4 "发送的待下载总页数信息报文字节4";
CM_ SG_ 2149154649 P2D_PrgInfo_Data5 "发送的待下载总页数信息报文字节5";
CM_ SG_ 2149154649 P2D_PrgInfo_Data6 "发送的待下载总页数信息报文字节6";
CM_ SG_ 2149154649 P2D_PrgInfo_Data7 "发送的待下载总页数信息报文字节7";
CM_ SG_ 2149154650 P2D_PrgInfo_Data0 "发送的待下载总页数信息报文字节0";
CM_ SG_ 2149154650 P2D_PrgInfo_Data1 "发送的待下载总页数信息报文字节1";
CM_ SG_ 2149154650 P2D_PrgInfo_Data2 "发送的待下载总页数信息报文字节2";
CM_ SG_ 2149154650 P2D_PrgInfo_Data3 "发送的待下载总页数信息报文字节3";
CM_ SG_ 2149154650 P2D_PrgInfo_Data4 "发送的待下载总页数信息报文字节4";
CM_ SG_ 2149154650 P2D_PrgInfo_Data5 "发送的待下载总页数信息报文字节5";
CM_ SG_ 2149154650 P2D_PrgInfo_Data6 "发送的待下载总页数信息报文字节6";
CM_ SG_ 2149154650 P2D_PrgInfo_Data7 "发送的待下载总页数信息报文字节7";
CM_ SG_ 2149154651 P2D_PrgInfo_Data0 "发送的待下载总页数信息报文字节0";
CM_ SG_ 2149154651 P2D_PrgInfo_Data1 "发送的待下载总页数信息报文字节1";
CM_ SG_ 2149154651 P2D_PrgInfo_Data2 "发送的待下载总页数信息报文字节2";
CM_ SG_ 2149154651 P2D_PrgInfo_Data3 "发送的待下载总页数信息报文字节3";
CM_ SG_ 2149154651 P2D_PrgInfo_Data4 "发送的待下载总页数信息报文字节4";
CM_ SG_ 2149154651 P2D_PrgInfo_Data5 "发送的待下载总页数信息报文字节5";
CM_ SG_ 2149154651 P2D_PrgInfo_Data6 "发送的待下载总页数信息报文字节6";
CM_ SG_ 2149154651 P2D_PrgInfo_Data7 "发送的待下载总页数信息报文字节7";
CM_ SG_ 2149154652 P2D_PrgInfo_Data0 "发送的待下载总页数信息报文字节0";
CM_ SG_ 2149154652 P2D_PrgInfo_Data1 "发送的待下载总页数信息报文字节1";
CM_ SG_ 2149154652 P2D_PrgInfo_Data2 "发送的待下载总页数信息报文字节2";
CM_ SG_ 2149154652 P2D_PrgInfo_Data3 "发送的待下载总页数信息报文字节3";
CM_ SG_ 2149154652 P2D_PrgInfo_Data4 "发送的待下载总页数信息报文字节4";
CM_ SG_ 2149154652 P2D_PrgInfo_Data5 "发送的待下载总页数信息报文字节5";
CM_ SG_ 2149154652 P2D_PrgInfo_Data6 "发送的待下载总页数信息报文字节6";
CM_ SG_ 2149154652 P2D_PrgInfo_Data7 "发送的待下载总页数信息报文字节7";
CM_ SG_ 2149154653 P2D_PrgInfo_Data0 "发送的待下载总页数信息报文字节0";
CM_ SG_ 2149154653 P2D_PrgInfo_Data1 "发送的待下载总页数信息报文字节1";
CM_ SG_ 2149154653 P2D_PrgInfo_Data2 "发送的待下载总页数信息报文字节2";
CM_ SG_ 2149154653 P2D_PrgInfo_Data3 "发送的待下载总页数信息报文字节3";
CM_ SG_ 2149154653 P2D_PrgInfo_Data4 "发送的待下载总页数信息报文字节4";
CM_ SG_ 2149154653 P2D_PrgInfo_Data5 "发送的待下载总页数信息报文字节5";
CM_ SG_ 2149154653 P2D_PrgInfo_Data6 "发送的待下载总页数信息报文字节6";
CM_ SG_ 2149154653 P2D_PrgInfo_Data7 "发送的待下载总页数信息报文字节7";
CM_ SG_ 2149154654 P2D_PrgInfo_Data0 "发送的待下载总页数信息报文字节0";
CM_ SG_ 2149154654 P2D_PrgInfo_Data1 "发送的待下载总页数信息报文字节1";
CM_ SG_ 2149154654 P2D_PrgInfo_Data2 "发送的待下载总页数信息报文字节2";
CM_ SG_ 2149154654 P2D_PrgInfo_Data3 "发送的待下载总页数信息报文字节3";
CM_ SG_ 2149154654 P2D_PrgInfo_Data4 "发送的待下载总页数信息报文字节4";
CM_ SG_ 2149154654 P2D_PrgInfo_Data5 "发送的待下载总页数信息报文字节5";
CM_ SG_ 2149154654 P2D_PrgInfo_Data6 "发送的待下载总页数信息报文字节6";
CM_ SG_ 2149154654 P2D_PrgInfo_Data7 "发送的待下载总页数信息报文字节7";
CM_ SG_ 2149154655 P2D_PrgInfo_Data0 "发送的待下载总页数信息报文字节0";
CM_ SG_ 2149154655 P2D_PrgInfo_Data1 "发送的待下载总页数信息报文字节1";
CM_ SG_ 2149154655 P2D_PrgInfo_Data2 "发送的待下载总页数信息报文字节2";
CM_ SG_ 2149154655 P2D_PrgInfo_Data3 "发送的待下载总页数信息报文字节3";
CM_ SG_ 2149154655 P2D_PrgInfo_Data4 "发送的待下载总页数信息报文字节4";
CM_ SG_ 2149154655 P2D_PrgInfo_Data5 "发送的待下载总页数信息报文字节5";
CM_ SG_ 2149154655 P2D_PrgInfo_Data6 "发送的待下载总页数信息报文字节6";
CM_ SG_ 2149154655 P2D_PrgInfo_Data7 "发送的待下载总页数信息报文字节7";
CM_ SG_ 2149154656 P2D_PrgInfo_Data0 "发送的待下载总页数信息报文字节0";
CM_ SG_ 2149154656 P2D_PrgInfo_Data1 "发送的待下载总页数信息报文字节1";
CM_ SG_ 2149154656 P2D_PrgInfo_Data2 "发送的待下载总页数信息报文字节2";
CM_ SG_ 2149154656 P2D_PrgInfo_Data3 "发送的待下载总页数信息报文字节3";
CM_ SG_ 2149154656 P2D_PrgInfo_Data4 "发送的待下载总页数信息报文字节4";
CM_ SG_ 2149154656 P2D_PrgInfo_Data5 "发送的待下载总页数信息报文字节5";
CM_ SG_ 2149154656 P2D_PrgInfo_Data6 "发送的待下载总页数信息报文字节6";
CM_ SG_ 2149154656 P2D_PrgInfo_Data7 "发送的待下载总页数信息报文字节7";
CM_ SG_ 2149154657 P2D_PrgInfo_Data0 "发送的待下载总页数信息报文字节0";
CM_ SG_ 2149154657 P2D_PrgInfo_Data1 "发送的待下载总页数信息报文字节1";
CM_ SG_ 2149154657 P2D_PrgInfo_Data2 "发送的待下载总页数信息报文字节2";
CM_ SG_ 2149154657 P2D_PrgInfo_Data3 "发送的待下载总页数信息报文字节3";
CM_ SG_ 2149154657 P2D_PrgInfo_Data4 "发送的待下载总页数信息报文字节4";
CM_ SG_ 2149154657 P2D_PrgInfo_Data5 "发送的待下载总页数信息报文字节5";
CM_ SG_ 2149154657 P2D_PrgInfo_Data6 "发送的待下载总页数信息报文字节6";
CM_ SG_ 2149154657 P2D_PrgInfo_Data7 "发送的待下载总页数信息报文字节7";
CM_ SG_ 2149154658 P2D_PrgInfo_Data0 "发送的待下载总页数信息报文字节0";
CM_ SG_ 2149154658 P2D_PrgInfo_Data1 "发送的待下载总页数信息报文字节1";
CM_ SG_ 2149154658 P2D_PrgInfo_Data2 "发送的待下载总页数信息报文字节2";
CM_ SG_ 2149154658 P2D_PrgInfo_Data3 "发送的待下载总页数信息报文字节3";
CM_ SG_ 2149154658 P2D_PrgInfo_Data4 "发送的待下载总页数信息报文字节4";
CM_ SG_ 2149154658 P2D_PrgInfo_Data5 "发送的待下载总页数信息报文字节5";
CM_ SG_ 2149154658 P2D_PrgInfo_Data6 "发送的待下载总页数信息报文字节6";
CM_ SG_ 2149154658 P2D_PrgInfo_Data7 "发送的待下载总页数信息报文字节7";
CM_ SG_ 2149154659 P2D_PrgInfo_Data0 "发送的待下载总页数信息报文字节0";
CM_ SG_ 2149154659 P2D_PrgInfo_Data1 "发送的待下载总页数信息报文字节1";
CM_ SG_ 2149154659 P2D_PrgInfo_Data2 "发送的待下载总页数信息报文字节2";
CM_ SG_ 2149154659 P2D_PrgInfo_Data3 "发送的待下载总页数信息报文字节3";
CM_ SG_ 2149154659 P2D_PrgInfo_Data4 "发送的待下载总页数信息报文字节4";
CM_ SG_ 2149154659 P2D_PrgInfo_Data5 "发送的待下载总页数信息报文字节5";
CM_ SG_ 2149154659 P2D_PrgInfo_Data6 "发送的待下载总页数信息报文字节6";
CM_ SG_ 2149154659 P2D_PrgInfo_Data7 "发送的待下载总页数信息报文字节7";
CM_ SG_ 2149154660 P2D_PrgInfo_Data0 "发送的待下载总页数信息报文字节0";
CM_ SG_ 2149154660 P2D_PrgInfo_Data1 "发送的待下载总页数信息报文字节1";
CM_ SG_ 2149154660 P2D_PrgInfo_Data2 "发送的待下载总页数信息报文字节2";
CM_ SG_ 2149154660 P2D_PrgInfo_Data3 "发送的待下载总页数信息报文字节3";
CM_ SG_ 2149154660 P2D_PrgInfo_Data4 "发送的待下载总页数信息报文字节4";
CM_ SG_ 2149154660 P2D_PrgInfo_Data5 "发送的待下载总页数信息报文字节5";
CM_ SG_ 2149154660 P2D_PrgInfo_Data6 "发送的待下载总页数信息报文字节6";
CM_ SG_ 2149154660 P2D_PrgInfo_Data7 "发送的待下载总页数信息报文字节7";
CM_ SG_ 2149154661 P2D_PrgInfo_Data0 "发送的待下载总页数信息报文字节0";
CM_ SG_ 2149154661 P2D_PrgInfo_Data1 "发送的待下载总页数信息报文字节1";
CM_ SG_ 2149154661 P2D_PrgInfo_Data2 "发送的待下载总页数信息报文字节2";
CM_ SG_ 2149154661 P2D_PrgInfo_Data3 "发送的待下载总页数信息报文字节3";
CM_ SG_ 2149154661 P2D_PrgInfo_Data4 "发送的待下载总页数信息报文字节4";
CM_ SG_ 2149154661 P2D_PrgInfo_Data5 "发送的待下载总页数信息报文字节5";
CM_ SG_ 2149154661 P2D_PrgInfo_Data6 "发送的待下载总页数信息报文字节6";
CM_ SG_ 2149154661 P2D_PrgInfo_Data7 "发送的待下载总页数信息报文字节7";
CM_ SG_ 2149154662 P2D_PrgInfo_Data0 "发送的待下载总页数信息报文字节0";
CM_ SG_ 2149154662 P2D_PrgInfo_Data1 "发送的待下载总页数信息报文字节1";
CM_ SG_ 2149154662 P2D_PrgInfo_Data2 "发送的待下载总页数信息报文字节2";
CM_ SG_ 2149154662 P2D_PrgInfo_Data3 "发送的待下载总页数信息报文字节3";
CM_ SG_ 2149154662 P2D_PrgInfo_Data4 "发送的待下载总页数信息报文字节4";
CM_ SG_ 2149154662 P2D_PrgInfo_Data5 "发送的待下载总页数信息报文字节5";
CM_ SG_ 2149154662 P2D_PrgInfo_Data6 "发送的待下载总页数信息报文字节6";
CM_ SG_ 2149154662 P2D_PrgInfo_Data7 "发送的待下载总页数信息报文字节7";
CM_ SG_ 2149154663 P2D_PrgInfo_Data0 "发送的待下载总页数信息报文字节0";
CM_ SG_ 2149154663 P2D_PrgInfo_Data1 "发送的待下载总页数信息报文字节1";
CM_ SG_ 2149154663 P2D_PrgInfo_Data2 "发送的待下载总页数信息报文字节2";
CM_ SG_ 2149154663 P2D_PrgInfo_Data3 "发送的待下载总页数信息报文字节3";
CM_ SG_ 2149154663 P2D_PrgInfo_Data4 "发送的待下载总页数信息报文字节4";
CM_ SG_ 2149154663 P2D_PrgInfo_Data5 "发送的待下载总页数信息报文字节5";
CM_ SG_ 2149154663 P2D_PrgInfo_Data6 "发送的待下载总页数信息报文字节6";
CM_ SG_ 2149154663 P2D_PrgInfo_Data7 "发送的待下载总页数信息报文字节7";
CM_ SG_ 2149154664 P2D_PrgInfo_Data0 "发送的待下载总页数信息报文字节0";
CM_ SG_ 2149154664 P2D_PrgInfo_Data1 "发送的待下载总页数信息报文字节1";
CM_ SG_ 2149154664 P2D_PrgInfo_Data2 "发送的待下载总页数信息报文字节2";
CM_ SG_ 2149154664 P2D_PrgInfo_Data3 "发送的待下载总页数信息报文字节3";
CM_ SG_ 2149154664 P2D_PrgInfo_Data4 "发送的待下载总页数信息报文字节4";
CM_ SG_ 2149154664 P2D_PrgInfo_Data5 "发送的待下载总页数信息报文字节5";
CM_ SG_ 2149154664 P2D_PrgInfo_Data6 "发送的待下载总页数信息报文字节6";
CM_ SG_ 2149154664 P2D_PrgInfo_Data7 "发送的待下载总页数信息报文字节7";
CM_ SG_ 2149154665 P2D_PrgInfo_Data0 "发送的待下载总页数信息报文字节0";
CM_ SG_ 2149154665 P2D_PrgInfo_Data1 "发送的待下载总页数信息报文字节1";
CM_ SG_ 2149154665 P2D_PrgInfo_Data2 "发送的待下载总页数信息报文字节2";
CM_ SG_ 2149154665 P2D_PrgInfo_Data3 "发送的待下载总页数信息报文字节3";
CM_ SG_ 2149154665 P2D_PrgInfo_Data4 "发送的待下载总页数信息报文字节4";
CM_ SG_ 2149154665 P2D_PrgInfo_Data5 "发送的待下载总页数信息报文字节5";
CM_ SG_ 2149154665 P2D_PrgInfo_Data6 "发送的待下载总页数信息报文字节6";
CM_ SG_ 2149154665 P2D_PrgInfo_Data7 "发送的待下载总页数信息报文字节7";
CM_ SG_ 2149154666 P2D_PrgInfo_Data0 "发送的待下载总页数信息报文字节0";
CM_ SG_ 2149154666 P2D_PrgInfo_Data1 "发送的待下载总页数信息报文字节1";
CM_ SG_ 2149154666 P2D_PrgInfo_Data2 "发送的待下载总页数信息报文字节2";
CM_ SG_ 2149154666 P2D_PrgInfo_Data3 "发送的待下载总页数信息报文字节3";
CM_ SG_ 2149154666 P2D_PrgInfo_Data4 "发送的待下载总页数信息报文字节4";
CM_ SG_ 2149154666 P2D_PrgInfo_Data5 "发送的待下载总页数信息报文字节5";
CM_ SG_ 2149154666 P2D_PrgInfo_Data6 "发送的待下载总页数信息报文字节6";
CM_ SG_ 2149154666 P2D_PrgInfo_Data7 "发送的待下载总页数信息报文字节7";
CM_ SG_ 2149154667 P2D_PrgInfo_Data0 "发送的待下载总页数信息报文字节0";
CM_ SG_ 2149154667 P2D_PrgInfo_Data1 "发送的待下载总页数信息报文字节1";
CM_ SG_ 2149154667 P2D_PrgInfo_Data2 "发送的待下载总页数信息报文字节2";
CM_ SG_ 2149154667 P2D_PrgInfo_Data3 "发送的待下载总页数信息报文字节3";
CM_ SG_ 2149154667 P2D_PrgInfo_Data4 "发送的待下载总页数信息报文字节4";
CM_ SG_ 2149154667 P2D_PrgInfo_Data5 "发送的待下载总页数信息报文字节5";
CM_ SG_ 2149154667 P2D_PrgInfo_Data6 "发送的待下载总页数信息报文字节6";
CM_ SG_ 2149154667 P2D_PrgInfo_Data7 "发送的待下载总页数信息报文字节7";
CM_ SG_ 2149154668 P2D_PrgInfo_Data0 "发送的待下载总页数信息报文字节0";
CM_ SG_ 2149154668 P2D_PrgInfo_Data1 "发送的待下载总页数信息报文字节1";
CM_ SG_ 2149154668 P2D_PrgInfo_Data2 "发送的待下载总页数信息报文字节2";
CM_ SG_ 2149154668 P2D_PrgInfo_Data3 "发送的待下载总页数信息报文字节3";
CM_ SG_ 2149154668 P2D_PrgInfo_Data4 "发送的待下载总页数信息报文字节4";
CM_ SG_ 2149154668 P2D_PrgInfo_Data5 "发送的待下载总页数信息报文字节5";
CM_ SG_ 2149154668 P2D_PrgInfo_Data6 "发送的待下载总页数信息报文字节6";
CM_ SG_ 2149154668 P2D_PrgInfo_Data7 "发送的待下载总页数信息报文字节7";
CM_ SG_ 2149154669 P2D_PrgInfo_Data0 "发送的待下载总页数信息报文字节0";
CM_ SG_ 2149154669 P2D_PrgInfo_Data1 "发送的待下载总页数信息报文字节1";
CM_ SG_ 2149154669 P2D_PrgInfo_Data2 "发送的待下载总页数信息报文字节2";
CM_ SG_ 2149154669 P2D_PrgInfo_Data3 "发送的待下载总页数信息报文字节3";
CM_ SG_ 2149154669 P2D_PrgInfo_Data4 "发送的待下载总页数信息报文字节4";
CM_ SG_ 2149154669 P2D_PrgInfo_Data5 "发送的待下载总页数信息报文字节5";
CM_ SG_ 2149154669 P2D_PrgInfo_Data6 "发送的待下载总页数信息报文字节6";
CM_ SG_ 2149154669 P2D_PrgInfo_Data7 "发送的待下载总页数信息报文字节7";
CM_ SG_ 2149154670 P2D_PrgInfo_Data0 "发送的待下载总页数信息报文字节0";
CM_ SG_ 2149154670 P2D_PrgInfo_Data1 "发送的待下载总页数信息报文字节1";
CM_ SG_ 2149154670 P2D_PrgInfo_Data2 "发送的待下载总页数信息报文字节2";
CM_ SG_ 2149154670 P2D_PrgInfo_Data3 "发送的待下载总页数信息报文字节3";
CM_ SG_ 2149154670 P2D_PrgInfo_Data4 "发送的待下载总页数信息报文字节4";
CM_ SG_ 2149154670 P2D_PrgInfo_Data5 "发送的待下载总页数信息报文字节5";
CM_ SG_ 2149154670 P2D_PrgInfo_Data6 "发送的待下载总页数信息报文字节6";
CM_ SG_ 2149154670 P2D_PrgInfo_Data7 "发送的待下载总页数信息报文字节7";
CM_ SG_ 2149154671 P2D_PrgInfo_Data0 "发送的待下载总页数信息报文字节0";
CM_ SG_ 2149154671 P2D_PrgInfo_Data1 "发送的待下载总页数信息报文字节1";
CM_ SG_ 2149154671 P2D_PrgInfo_Data2 "发送的待下载总页数信息报文字节2";
CM_ SG_ 2149154671 P2D_PrgInfo_Data3 "发送的待下载总页数信息报文字节3";
CM_ SG_ 2149154671 P2D_PrgInfo_Data4 "发送的待下载总页数信息报文字节4";
CM_ SG_ 2149154671 P2D_PrgInfo_Data5 "发送的待下载总页数信息报文字节5";
CM_ SG_ 2149154671 P2D_PrgInfo_Data6 "发送的待下载总页数信息报文字节6";
CM_ SG_ 2149154671 P2D_PrgInfo_Data7 "发送的待下载总页数信息报文字节7";
CM_ SG_ 2149154672 P2D_PrgInfo_Data0 "发送的待下载总页数信息报文字节0";
CM_ SG_ 2149154672 P2D_PrgInfo_Data1 "发送的待下载总页数信息报文字节1";
CM_ SG_ 2149154672 P2D_PrgInfo_Data2 "发送的待下载总页数信息报文字节2";
CM_ SG_ 2149154672 P2D_PrgInfo_Data3 "发送的待下载总页数信息报文字节3";
CM_ SG_ 2149154672 P2D_PrgInfo_Data4 "发送的待下载总页数信息报文字节4";
CM_ SG_ 2149154672 P2D_PrgInfo_Data5 "发送的待下载总页数信息报文字节5";
CM_ SG_ 2149154672 P2D_PrgInfo_Data6 "发送的待下载总页数信息报文字节6";
CM_ SG_ 2149154672 P2D_PrgInfo_Data7 "发送的待下载总页数信息报文字节7";
CM_ SG_ 2149154673 P2D_PrgInfo_Data0 "发送的待下载总页数信息报文字节0";
CM_ SG_ 2149154673 P2D_PrgInfo_Data1 "发送的待下载总页数信息报文字节1";
CM_ SG_ 2149154673 P2D_PrgInfo_Data2 "发送的待下载总页数信息报文字节2";
CM_ SG_ 2149154673 P2D_PrgInfo_Data3 "发送的待下载总页数信息报文字节3";
CM_ SG_ 2149154673 P2D_PrgInfo_Data4 "发送的待下载总页数信息报文字节4";
CM_ SG_ 2149154673 P2D_PrgInfo_Data5 "发送的待下载总页数信息报文字节5";
CM_ SG_ 2149154673 P2D_PrgInfo_Data6 "发送的待下载总页数信息报文字节6";
CM_ SG_ 2149154673 P2D_PrgInfo_Data7 "发送的待下载总页数信息报文字节7";
CM_ SG_ 2149154674 P2D_PrgInfo_Data0 "发送的待下载总页数信息报文字节0";
CM_ SG_ 2149154674 P2D_PrgInfo_Data1 "发送的待下载总页数信息报文字节1";
CM_ SG_ 2149154674 P2D_PrgInfo_Data2 "发送的待下载总页数信息报文字节2";
CM_ SG_ 2149154674 P2D_PrgInfo_Data3 "发送的待下载总页数信息报文字节3";
CM_ SG_ 2149154674 P2D_PrgInfo_Data4 "发送的待下载总页数信息报文字节4";
CM_ SG_ 2149154674 P2D_PrgInfo_Data5 "发送的待下载总页数信息报文字节5";
CM_ SG_ 2149154674 P2D_PrgInfo_Data6 "发送的待下载总页数信息报文字节6";
CM_ SG_ 2149154674 P2D_PrgInfo_Data7 "发送的待下载总页数信息报文字节7";
CM_ SG_ 2149154675 P2D_PrgInfo_Data0 "发送的待下载总页数信息报文字节0";
CM_ SG_ 2149154675 P2D_PrgInfo_Data1 "发送的待下载总页数信息报文字节1";
CM_ SG_ 2149154675 P2D_PrgInfo_Data2 "发送的待下载总页数信息报文字节2";
CM_ SG_ 2149154675 P2D_PrgInfo_Data3 "发送的待下载总页数信息报文字节3";
CM_ SG_ 2149154675 P2D_PrgInfo_Data4 "发送的待下载总页数信息报文字节4";
CM_ SG_ 2149154675 P2D_PrgInfo_Data5 "发送的待下载总页数信息报文字节5";
CM_ SG_ 2149154675 P2D_PrgInfo_Data6 "发送的待下载总页数信息报文字节6";
CM_ SG_ 2149154675 P2D_PrgInfo_Data7 "发送的待下载总页数信息报文字节7";
CM_ SG_ 2149154676 P2D_PrgInfo_Data0 "发送的待下载总页数信息报文字节0";
CM_ SG_ 2149154676 P2D_PrgInfo_Data1 "发送的待下载总页数信息报文字节1";
CM_ SG_ 2149154676 P2D_PrgInfo_Data2 "发送的待下载总页数信息报文字节2";
CM_ SG_ 2149154676 P2D_PrgInfo_Data3 "发送的待下载总页数信息报文字节3";
CM_ SG_ 2149154676 P2D_PrgInfo_Data4 "发送的待下载总页数信息报文字节4";
CM_ SG_ 2149154676 P2D_PrgInfo_Data5 "发送的待下载总页数信息报文字节5";
CM_ SG_ 2149154676 P2D_PrgInfo_Data6 "发送的待下载总页数信息报文字节6";
CM_ SG_ 2149154676 P2D_PrgInfo_Data7 "发送的待下载总页数信息报文字节7";
CM_ SG_ 2149154677 P2D_PrgInfo_Data0 "发送的待下载总页数信息报文字节0";
CM_ SG_ 2149154677 P2D_PrgInfo_Data1 "发送的待下载总页数信息报文字节1";
CM_ SG_ 2149154677 P2D_PrgInfo_Data2 "发送的待下载总页数信息报文字节2";
CM_ SG_ 2149154677 P2D_PrgInfo_Data3 "发送的待下载总页数信息报文字节3";
CM_ SG_ 2149154677 P2D_PrgInfo_Data4 "发送的待下载总页数信息报文字节4";
CM_ SG_ 2149154677 P2D_PrgInfo_Data5 "发送的待下载总页数信息报文字节5";
CM_ SG_ 2149154677 P2D_PrgInfo_Data6 "发送的待下载总页数信息报文字节6";
CM_ SG_ 2149154677 P2D_PrgInfo_Data7 "发送的待下载总页数信息报文字节7";
CM_ SG_ 2149154678 P2D_PrgInfo_Data0 "发送的待下载总页数信息报文字节0";
CM_ SG_ 2149154678 P2D_PrgInfo_Data1 "发送的待下载总页数信息报文字节1";
CM_ SG_ 2149154678 P2D_PrgInfo_Data2 "发送的待下载总页数信息报文字节2";
CM_ SG_ 2149154678 P2D_PrgInfo_Data3 "发送的待下载总页数信息报文字节3";
CM_ SG_ 2149154678 P2D_PrgInfo_Data4 "发送的待下载总页数信息报文字节4";
CM_ SG_ 2149154678 P2D_PrgInfo_Data5 "发送的待下载总页数信息报文字节5";
CM_ SG_ 2149154678 P2D_PrgInfo_Data6 "发送的待下载总页数信息报文字节6";
CM_ SG_ 2149154678 P2D_PrgInfo_Data7 "发送的待下载总页数信息报文字节7";
CM_ SG_ 2149154679 P2D_PrgInfo_Data0 "发送的待下载总页数信息报文字节0";
CM_ SG_ 2149154679 P2D_PrgInfo_Data1 "发送的待下载总页数信息报文字节1";
CM_ SG_ 2149154679 P2D_PrgInfo_Data2 "发送的待下载总页数信息报文字节2";
CM_ SG_ 2149154679 P2D_PrgInfo_Data3 "发送的待下载总页数信息报文字节3";
CM_ SG_ 2149154679 P2D_PrgInfo_Data4 "发送的待下载总页数信息报文字节4";
CM_ SG_ 2149154679 P2D_PrgInfo_Data5 "发送的待下载总页数信息报文字节5";
CM_ SG_ 2149154679 P2D_PrgInfo_Data6 "发送的待下载总页数信息报文字节6";
CM_ SG_ 2149154679 P2D_PrgInfo_Data7 "发送的待下载总页数信息报文字节7";
CM_ SG_ 2149154680 P2D_PrgInfo_Data0 "发送的待下载总页数信息报文字节0";
CM_ SG_ 2149154680 P2D_PrgInfo_Data1 "发送的待下载总页数信息报文字节1";
CM_ SG_ 2149154680 P2D_PrgInfo_Data2 "发送的待下载总页数信息报文字节2";
CM_ SG_ 2149154680 P2D_PrgInfo_Data3 "发送的待下载总页数信息报文字节3";
CM_ SG_ 2149154680 P2D_PrgInfo_Data4 "发送的待下载总页数信息报文字节4";
CM_ SG_ 2149154680 P2D_PrgInfo_Data5 "发送的待下载总页数信息报文字节5";
CM_ SG_ 2149154680 P2D_PrgInfo_Data6 "发送的待下载总页数信息报文字节6";
CM_ SG_ 2149154680 P2D_PrgInfo_Data7 "发送的待下载总页数信息报文字节7";
CM_ SG_ 2149154681 P2D_PrgInfo_Data0 "发送的待下载总页数信息报文字节0";
CM_ SG_ 2149154681 P2D_PrgInfo_Data1 "发送的待下载总页数信息报文字节1";
CM_ SG_ 2149154681 P2D_PrgInfo_Data2 "发送的待下载总页数信息报文字节2";
CM_ SG_ 2149154681 P2D_PrgInfo_Data3 "发送的待下载总页数信息报文字节3";
CM_ SG_ 2149154681 P2D_PrgInfo_Data4 "发送的待下载总页数信息报文字节4";
CM_ SG_ 2149154681 P2D_PrgInfo_Data5 "发送的待下载总页数信息报文字节5";
CM_ SG_ 2149154681 P2D_PrgInfo_Data6 "发送的待下载总页数信息报文字节6";
CM_ SG_ 2149154681 P2D_PrgInfo_Data7 "发送的待下载总页数信息报文字节7";
CM_ SG_ 2149154682 P2D_PrgInfo_Data0 "发送的待下载总页数信息报文字节0";
CM_ SG_ 2149154682 P2D_PrgInfo_Data1 "发送的待下载总页数信息报文字节1";
CM_ SG_ 2149154682 P2D_PrgInfo_Data2 "发送的待下载总页数信息报文字节2";
CM_ SG_ 2149154682 P2D_PrgInfo_Data3 "发送的待下载总页数信息报文字节3";
CM_ SG_ 2149154682 P2D_PrgInfo_Data4 "发送的待下载总页数信息报文字节4";
CM_ SG_ 2149154682 P2D_PrgInfo_Data5 "发送的待下载总页数信息报文字节5";
CM_ SG_ 2149154682 P2D_PrgInfo_Data6 "发送的待下载总页数信息报文字节6";
CM_ SG_ 2149154682 P2D_PrgInfo_Data7 "发送的待下载总页数信息报文字节7";
CM_ SG_ 2149154683 P2D_PrgInfo_Data0 "发送的待下载总页数信息报文字节0";
CM_ SG_ 2149154683 P2D_PrgInfo_Data1 "发送的待下载总页数信息报文字节1";
CM_ SG_ 2149154683 P2D_PrgInfo_Data2 "发送的待下载总页数信息报文字节2";
CM_ SG_ 2149154683 P2D_PrgInfo_Data3 "发送的待下载总页数信息报文字节3";
CM_ SG_ 2149154683 P2D_PrgInfo_Data4 "发送的待下载总页数信息报文字节4";
CM_ SG_ 2149154683 P2D_PrgInfo_Data5 "发送的待下载总页数信息报文字节5";
CM_ SG_ 2149154683 P2D_PrgInfo_Data6 "发送的待下载总页数信息报文字节6";
CM_ SG_ 2149154683 P2D_PrgInfo_Data7 "发送的待下载总页数信息报文字节7";
CM_ SG_ 2149154684 P2D_PrgInfo_Data0 "发送的待下载总页数信息报文字节0";
CM_ SG_ 2149154684 P2D_PrgInfo_Data1 "发送的待下载总页数信息报文字节1";
CM_ SG_ 2149154684 P2D_PrgInfo_Data2 "发送的待下载总页数信息报文字节2";
CM_ SG_ 2149154684 P2D_PrgInfo_Data3 "发送的待下载总页数信息报文字节3";
CM_ SG_ 2149154684 P2D_PrgInfo_Data4 "发送的待下载总页数信息报文字节4";
CM_ SG_ 2149154684 P2D_PrgInfo_Data5 "发送的待下载总页数信息报文字节5";
CM_ SG_ 2149154684 P2D_PrgInfo_Data6 "发送的待下载总页数信息报文字节6";
CM_ SG_ 2149154684 P2D_PrgInfo_Data7 "发送的待下载总页数信息报文字节7";
CM_ SG_ 2149154685 P2D_PrgInfo_Data0 "发送的待下载总页数信息报文字节0";
CM_ SG_ 2149154685 P2D_PrgInfo_Data1 "发送的待下载总页数信息报文字节1";
CM_ SG_ 2149154685 P2D_PrgInfo_Data2 "发送的待下载总页数信息报文字节2";
CM_ SG_ 2149154685 P2D_PrgInfo_Data3 "发送的待下载总页数信息报文字节3";
CM_ SG_ 2149154685 P2D_PrgInfo_Data4 "发送的待下载总页数信息报文字节4";
CM_ SG_ 2149154685 P2D_PrgInfo_Data5 "发送的待下载总页数信息报文字节5";
CM_ SG_ 2149154685 P2D_PrgInfo_Data6 "发送的待下载总页数信息报文字节6";
CM_ SG_ 2149154685 P2D_PrgInfo_Data7 "发送的待下载总页数信息报文字节7";
CM_ SG_ 2149154686 P2D_PrgInfo_Data0 "发送的待下载总页数信息报文字节0";
CM_ SG_ 2149154686 P2D_PrgInfo_Data1 "发送的待下载总页数信息报文字节1";
CM_ SG_ 2149154686 P2D_PrgInfo_Data2 "发送的待下载总页数信息报文字节2";
CM_ SG_ 2149154686 P2D_PrgInfo_Data3 "发送的待下载总页数信息报文字节3";
CM_ SG_ 2149154686 P2D_PrgInfo_Data4 "发送的待下载总页数信息报文字节4";
CM_ SG_ 2149154686 P2D_PrgInfo_Data5 "发送的待下载总页数信息报文字节5";
CM_ SG_ 2149154686 P2D_PrgInfo_Data6 "发送的待下载总页数信息报文字节6";
CM_ SG_ 2149154686 P2D_PrgInfo_Data7 "发送的待下载总页数信息报文字节7";
CM_ SG_ 2149154687 P2D_PrgInfo_Data0 "发送的待下载总页数信息报文字节0";
CM_ SG_ 2149154687 P2D_PrgInfo_Data1 "发送的待下载总页数信息报文字节1";
CM_ SG_ 2149154687 P2D_PrgInfo_Data2 "发送的待下载总页数信息报文字节2";
CM_ SG_ 2149154687 P2D_PrgInfo_Data3 "发送的待下载总页数信息报文字节3";
CM_ SG_ 2149154687 P2D_PrgInfo_Data4 "发送的待下载总页数信息报文字节4";
CM_ SG_ 2149154687 P2D_PrgInfo_Data5 "发送的待下载总页数信息报文字节5";
CM_ SG_ 2149154687 P2D_PrgInfo_Data6 "发送的待下载总页数信息报文字节6";
CM_ SG_ 2149154687 P2D_PrgInfo_Data7 "发送的待下载总页数信息报文字节7";
CM_ SG_ 2149220161 P2D_DLoadInfo_Data0 "发送的flash程序页下载握手指令报文字节0";
CM_ SG_ 2149220161 P2D_DLoadInfo_Data1 "发送的flash程序页下载握手指令报文字节1";
CM_ SG_ 2149220161 P2D_DLoadInfo_Data2 "发送的flash程序页下载握手指令报文字节2";
CM_ SG_ 2149220161 P2D_DLoadInfo_Data3 "发送的flash程序页下载握手指令报文字节3";
CM_ SG_ 2149220161 P2D_DLoadInfo_Data4 "发送的flash程序页下载握手指令报文字节4";
CM_ SG_ 2149220161 P2D_DLoadInfo_Data5 "发送的flash程序页下载握手指令报文字节5";
CM_ SG_ 2149220161 P2D_DLoadInfo_Data6 "发送的flash程序页下载握手指令报文字节6";
CM_ SG_ 2149220161 P2D_DLoadInfo_Data7 "发送的flash程序页下载握手指令报文字节7";
CM_ SG_ 2149220162 P2D_DLoadInfo_Data0 "发送的flash程序页下载握手指令报文字节0";
CM_ SG_ 2149220162 P2D_DLoadInfo_Data1 "发送的flash程序页下载握手指令报文字节1";
CM_ SG_ 2149220162 P2D_DLoadInfo_Data2 "发送的flash程序页下载握手指令报文字节2";
CM_ SG_ 2149220162 P2D_DLoadInfo_Data3 "发送的flash程序页下载握手指令报文字节3";
CM_ SG_ 2149220162 P2D_DLoadInfo_Data4 "发送的flash程序页下载握手指令报文字节4";
CM_ SG_ 2149220162 P2D_DLoadInfo_Data5 "发送的flash程序页下载握手指令报文字节5";
CM_ SG_ 2149220162 P2D_DLoadInfo_Data6 "发送的flash程序页下载握手指令报文字节6";
CM_ SG_ 2149220162 P2D_DLoadInfo_Data7 "发送的flash程序页下载握手指令报文字节7";
CM_ SG_ 2149220163 P2D_DLoadInfo_Data0 "发送的flash程序页下载握手指令报文字节0";
CM_ SG_ 2149220163 P2D_DLoadInfo_Data1 "发送的flash程序页下载握手指令报文字节1";
CM_ SG_ 2149220163 P2D_DLoadInfo_Data2 "发送的flash程序页下载握手指令报文字节2";
CM_ SG_ 2149220163 P2D_DLoadInfo_Data3 "发送的flash程序页下载握手指令报文字节3";
CM_ SG_ 2149220163 P2D_DLoadInfo_Data4 "发送的flash程序页下载握手指令报文字节4";
CM_ SG_ 2149220163 P2D_DLoadInfo_Data5 "发送的flash程序页下载握手指令报文字节5";
CM_ SG_ 2149220163 P2D_DLoadInfo_Data6 "发送的flash程序页下载握手指令报文字节6";
CM_ SG_ 2149220163 P2D_DLoadInfo_Data7 "发送的flash程序页下载握手指令报文字节7";
CM_ SG_ 2149220164 P2D_DLoadInfo_Data0 "发送的flash程序页下载握手指令报文字节0";
CM_ SG_ 2149220164 P2D_DLoadInfo_Data1 "发送的flash程序页下载握手指令报文字节1";
CM_ SG_ 2149220164 P2D_DLoadInfo_Data2 "发送的flash程序页下载握手指令报文字节2";
CM_ SG_ 2149220164 P2D_DLoadInfo_Data3 "发送的flash程序页下载握手指令报文字节3";
CM_ SG_ 2149220164 P2D_DLoadInfo_Data4 "发送的flash程序页下载握手指令报文字节4";
CM_ SG_ 2149220164 P2D_DLoadInfo_Data5 "发送的flash程序页下载握手指令报文字节5";
CM_ SG_ 2149220164 P2D_DLoadInfo_Data6 "发送的flash程序页下载握手指令报文字节6";
CM_ SG_ 2149220164 P2D_DLoadInfo_Data7 "发送的flash程序页下载握手指令报文字节7";
CM_ SG_ 2149220165 P2D_DLoadInfo_Data0 "发送的flash程序页下载握手指令报文字节0";
CM_ SG_ 2149220165 P2D_DLoadInfo_Data1 "发送的flash程序页下载握手指令报文字节1";
CM_ SG_ 2149220165 P2D_DLoadInfo_Data2 "发送的flash程序页下载握手指令报文字节2";
CM_ SG_ 2149220165 P2D_DLoadInfo_Data3 "发送的flash程序页下载握手指令报文字节3";
CM_ SG_ 2149220165 P2D_DLoadInfo_Data4 "发送的flash程序页下载握手指令报文字节4";
CM_ SG_ 2149220165 P2D_DLoadInfo_Data5 "发送的flash程序页下载握手指令报文字节5";
CM_ SG_ 2149220165 P2D_DLoadInfo_Data6 "发送的flash程序页下载握手指令报文字节6";
CM_ SG_ 2149220165 P2D_DLoadInfo_Data7 "发送的flash程序页下载握手指令报文字节7";
CM_ SG_ 2149220166 P2D_DLoadInfo_Data0 "发送的flash程序页下载握手指令报文字节0";
CM_ SG_ 2149220166 P2D_DLoadInfo_Data1 "发送的flash程序页下载握手指令报文字节1";
CM_ SG_ 2149220166 P2D_DLoadInfo_Data2 "发送的flash程序页下载握手指令报文字节2";
CM_ SG_ 2149220166 P2D_DLoadInfo_Data3 "发送的flash程序页下载握手指令报文字节3";
CM_ SG_ 2149220166 P2D_DLoadInfo_Data4 "发送的flash程序页下载握手指令报文字节4";
CM_ SG_ 2149220166 P2D_DLoadInfo_Data5 "发送的flash程序页下载握手指令报文字节5";
CM_ SG_ 2149220166 P2D_DLoadInfo_Data6 "发送的flash程序页下载握手指令报文字节6";
CM_ SG_ 2149220166 P2D_DLoadInfo_Data7 "发送的flash程序页下载握手指令报文字节7";
CM_ SG_ 2149220167 P2D_DLoadInfo_Data0 "发送的flash程序页下载握手指令报文字节0";
CM_ SG_ 2149220167 P2D_DLoadInfo_Data1 "发送的flash程序页下载握手指令报文字节1";
CM_ SG_ 2149220167 P2D_DLoadInfo_Data2 "发送的flash程序页下载握手指令报文字节2";
CM_ SG_ 2149220167 P2D_DLoadInfo_Data3 "发送的flash程序页下载握手指令报文字节3";
CM_ SG_ 2149220167 P2D_DLoadInfo_Data4 "发送的flash程序页下载握手指令报文字节4";
CM_ SG_ 2149220167 P2D_DLoadInfo_Data5 "发送的flash程序页下载握手指令报文字节5";
CM_ SG_ 2149220167 P2D_DLoadInfo_Data6 "发送的flash程序页下载握手指令报文字节6";
CM_ SG_ 2149220167 P2D_DLoadInfo_Data7 "发送的flash程序页下载握手指令报文字节7";
CM_ SG_ 2149220168 P2D_DLoadInfo_Data0 "发送的flash程序页下载握手指令报文字节0";
CM_ SG_ 2149220168 P2D_DLoadInfo_Data1 "发送的flash程序页下载握手指令报文字节1";
CM_ SG_ 2149220168 P2D_DLoadInfo_Data2 "发送的flash程序页下载握手指令报文字节2";
CM_ SG_ 2149220168 P2D_DLoadInfo_Data3 "发送的flash程序页下载握手指令报文字节3";
CM_ SG_ 2149220168 P2D_DLoadInfo_Data4 "发送的flash程序页下载握手指令报文字节4";
CM_ SG_ 2149220168 P2D_DLoadInfo_Data5 "发送的flash程序页下载握手指令报文字节5";
CM_ SG_ 2149220168 P2D_DLoadInfo_Data6 "发送的flash程序页下载握手指令报文字节6";
CM_ SG_ 2149220168 P2D_DLoadInfo_Data7 "发送的flash程序页下载握手指令报文字节7";
CM_ SG_ 2149220169 P2D_DLoadInfo_Data0 "发送的flash程序页下载握手指令报文字节0";
CM_ SG_ 2149220169 P2D_DLoadInfo_Data1 "发送的flash程序页下载握手指令报文字节1";
CM_ SG_ 2149220169 P2D_DLoadInfo_Data2 "发送的flash程序页下载握手指令报文字节2";
CM_ SG_ 2149220169 P2D_DLoadInfo_Data3 "发送的flash程序页下载握手指令报文字节3";
CM_ SG_ 2149220169 P2D_DLoadInfo_Data4 "发送的flash程序页下载握手指令报文字节4";
CM_ SG_ 2149220169 P2D_DLoadInfo_Data5 "发送的flash程序页下载握手指令报文字节5";
CM_ SG_ 2149220169 P2D_DLoadInfo_Data6 "发送的flash程序页下载握手指令报文字节6";
CM_ SG_ 2149220169 P2D_DLoadInfo_Data7 "发送的flash程序页下载握手指令报文字节7";
CM_ SG_ 2149220170 P2D_DLoadInfo_Data0 "发送的flash程序页下载握手指令报文字节0";
CM_ SG_ 2149220170 P2D_DLoadInfo_Data1 "发送的flash程序页下载握手指令报文字节1";
CM_ SG_ 2149220170 P2D_DLoadInfo_Data2 "发送的flash程序页下载握手指令报文字节2";
CM_ SG_ 2149220170 P2D_DLoadInfo_Data3 "发送的flash程序页下载握手指令报文字节3";
CM_ SG_ 2149220170 P2D_DLoadInfo_Data4 "发送的flash程序页下载握手指令报文字节4";
CM_ SG_ 2149220170 P2D_DLoadInfo_Data5 "发送的flash程序页下载握手指令报文字节5";
CM_ SG_ 2149220170 P2D_DLoadInfo_Data6 "发送的flash程序页下载握手指令报文字节6";
CM_ SG_ 2149220170 P2D_DLoadInfo_Data7 "发送的flash程序页下载握手指令报文字节7";
CM_ SG_ 2149220171 P2D_DLoadInfo_Data0 "发送的flash程序页下载握手指令报文字节0";
CM_ SG_ 2149220171 P2D_DLoadInfo_Data1 "发送的flash程序页下载握手指令报文字节1";
CM_ SG_ 2149220171 P2D_DLoadInfo_Data2 "发送的flash程序页下载握手指令报文字节2";
CM_ SG_ 2149220171 P2D_DLoadInfo_Data3 "发送的flash程序页下载握手指令报文字节3";
CM_ SG_ 2149220171 P2D_DLoadInfo_Data4 "发送的flash程序页下载握手指令报文字节4";
CM_ SG_ 2149220171 P2D_DLoadInfo_Data5 "发送的flash程序页下载握手指令报文字节5";
CM_ SG_ 2149220171 P2D_DLoadInfo_Data6 "发送的flash程序页下载握手指令报文字节6";
CM_ SG_ 2149220171 P2D_DLoadInfo_Data7 "发送的flash程序页下载握手指令报文字节7";
CM_ SG_ 2149220172 P2D_DLoadInfo_Data0 "发送的flash程序页下载握手指令报文字节0";
CM_ SG_ 2149220172 P2D_DLoadInfo_Data1 "发送的flash程序页下载握手指令报文字节1";
CM_ SG_ 2149220172 P2D_DLoadInfo_Data2 "发送的flash程序页下载握手指令报文字节2";
CM_ SG_ 2149220172 P2D_DLoadInfo_Data3 "发送的flash程序页下载握手指令报文字节3";
CM_ SG_ 2149220172 P2D_DLoadInfo_Data4 "发送的flash程序页下载握手指令报文字节4";
CM_ SG_ 2149220172 P2D_DLoadInfo_Data5 "发送的flash程序页下载握手指令报文字节5";
CM_ SG_ 2149220172 P2D_DLoadInfo_Data6 "发送的flash程序页下载握手指令报文字节6";
CM_ SG_ 2149220172 P2D_DLoadInfo_Data7 "发送的flash程序页下载握手指令报文字节7";
CM_ SG_ 2149220173 P2D_DLoadInfo_Data0 "发送的flash程序页下载握手指令报文字节0";
CM_ SG_ 2149220173 P2D_DLoadInfo_Data1 "发送的flash程序页下载握手指令报文字节1";
CM_ SG_ 2149220173 P2D_DLoadInfo_Data2 "发送的flash程序页下载握手指令报文字节2";
CM_ SG_ 2149220173 P2D_DLoadInfo_Data3 "发送的flash程序页下载握手指令报文字节3";
CM_ SG_ 2149220173 P2D_DLoadInfo_Data4 "发送的flash程序页下载握手指令报文字节4";
CM_ SG_ 2149220173 P2D_DLoadInfo_Data5 "发送的flash程序页下载握手指令报文字节5";
CM_ SG_ 2149220173 P2D_DLoadInfo_Data6 "发送的flash程序页下载握手指令报文字节6";
CM_ SG_ 2149220173 P2D_DLoadInfo_Data7 "发送的flash程序页下载握手指令报文字节7";
CM_ SG_ 2149220174 P2D_DLoadInfo_Data0 "发送的flash程序页下载握手指令报文字节0";
CM_ SG_ 2149220174 P2D_DLoadInfo_Data1 "发送的flash程序页下载握手指令报文字节1";
CM_ SG_ 2149220174 P2D_DLoadInfo_Data2 "发送的flash程序页下载握手指令报文字节2";
CM_ SG_ 2149220174 P2D_DLoadInfo_Data3 "发送的flash程序页下载握手指令报文字节3";
CM_ SG_ 2149220174 P2D_DLoadInfo_Data4 "发送的flash程序页下载握手指令报文字节4";
CM_ SG_ 2149220174 P2D_DLoadInfo_Data5 "发送的flash程序页下载握手指令报文字节5";
CM_ SG_ 2149220174 P2D_DLoadInfo_Data6 "发送的flash程序页下载握手指令报文字节6";
CM_ SG_ 2149220174 P2D_DLoadInfo_Data7 "发送的flash程序页下载握手指令报文字节7";
CM_ SG_ 2149220175 P2D_DLoadInfo_Data0 "发送的flash程序页下载握手指令报文字节0";
CM_ SG_ 2149220175 P2D_DLoadInfo_Data1 "发送的flash程序页下载握手指令报文字节1";
CM_ SG_ 2149220175 P2D_DLoadInfo_Data2 "发送的flash程序页下载握手指令报文字节2";
CM_ SG_ 2149220175 P2D_DLoadInfo_Data3 "发送的flash程序页下载握手指令报文字节3";
CM_ SG_ 2149220175 P2D_DLoadInfo_Data4 "发送的flash程序页下载握手指令报文字节4";
CM_ SG_ 2149220175 P2D_DLoadInfo_Data5 "发送的flash程序页下载握手指令报文字节5";
CM_ SG_ 2149220175 P2D_DLoadInfo_Data6 "发送的flash程序页下载握手指令报文字节6";
CM_ SG_ 2149220175 P2D_DLoadInfo_Data7 "发送的flash程序页下载握手指令报文字节7";
CM_ SG_ 2149220176 P2D_DLoadInfo_Data0 "发送的flash程序页下载握手指令报文字节0";
CM_ SG_ 2149220176 P2D_DLoadInfo_Data1 "发送的flash程序页下载握手指令报文字节1";
CM_ SG_ 2149220176 P2D_DLoadInfo_Data2 "发送的flash程序页下载握手指令报文字节2";
CM_ SG_ 2149220176 P2D_DLoadInfo_Data3 "发送的flash程序页下载握手指令报文字节3";
CM_ SG_ 2149220176 P2D_DLoadInfo_Data4 "发送的flash程序页下载握手指令报文字节4";
CM_ SG_ 2149220176 P2D_DLoadInfo_Data5 "发送的flash程序页下载握手指令报文字节5";
CM_ SG_ 2149220176 P2D_DLoadInfo_Data6 "发送的flash程序页下载握手指令报文字节6";
CM_ SG_ 2149220176 P2D_DLoadInfo_Data7 "发送的flash程序页下载握手指令报文字节7";
CM_ SG_ 2149220177 P2D_DLoadInfo_Data0 "发送的flash程序页下载握手指令报文字节0";
CM_ SG_ 2149220177 P2D_DLoadInfo_Data1 "发送的flash程序页下载握手指令报文字节1";
CM_ SG_ 2149220177 P2D_DLoadInfo_Data2 "发送的flash程序页下载握手指令报文字节2";
CM_ SG_ 2149220177 P2D_DLoadInfo_Data3 "发送的flash程序页下载握手指令报文字节3";
CM_ SG_ 2149220177 P2D_DLoadInfo_Data4 "发送的flash程序页下载握手指令报文字节4";
CM_ SG_ 2149220177 P2D_DLoadInfo_Data5 "发送的flash程序页下载握手指令报文字节5";
CM_ SG_ 2149220177 P2D_DLoadInfo_Data6 "发送的flash程序页下载握手指令报文字节6";
CM_ SG_ 2149220177 P2D_DLoadInfo_Data7 "发送的flash程序页下载握手指令报文字节7";
CM_ SG_ 2149220178 P2D_DLoadInfo_Data0 "发送的flash程序页下载握手指令报文字节0";
CM_ SG_ 2149220178 P2D_DLoadInfo_Data1 "发送的flash程序页下载握手指令报文字节1";
CM_ SG_ 2149220178 P2D_DLoadInfo_Data2 "发送的flash程序页下载握手指令报文字节2";
CM_ SG_ 2149220178 P2D_DLoadInfo_Data3 "发送的flash程序页下载握手指令报文字节3";
CM_ SG_ 2149220178 P2D_DLoadInfo_Data4 "发送的flash程序页下载握手指令报文字节4";
CM_ SG_ 2149220178 P2D_DLoadInfo_Data5 "发送的flash程序页下载握手指令报文字节5";
CM_ SG_ 2149220178 P2D_DLoadInfo_Data6 "发送的flash程序页下载握手指令报文字节6";
CM_ SG_ 2149220178 P2D_DLoadInfo_Data7 "发送的flash程序页下载握手指令报文字节7";
CM_ SG_ 2149220179 P2D_DLoadInfo_Data0 "发送的flash程序页下载握手指令报文字节0";
CM_ SG_ 2149220179 P2D_DLoadInfo_Data1 "发送的flash程序页下载握手指令报文字节1";
CM_ SG_ 2149220179 P2D_DLoadInfo_Data2 "发送的flash程序页下载握手指令报文字节2";
CM_ SG_ 2149220179 P2D_DLoadInfo_Data3 "发送的flash程序页下载握手指令报文字节3";
CM_ SG_ 2149220179 P2D_DLoadInfo_Data4 "发送的flash程序页下载握手指令报文字节4";
CM_ SG_ 2149220179 P2D_DLoadInfo_Data5 "发送的flash程序页下载握手指令报文字节5";
CM_ SG_ 2149220179 P2D_DLoadInfo_Data6 "发送的flash程序页下载握手指令报文字节6";
CM_ SG_ 2149220179 P2D_DLoadInfo_Data7 "发送的flash程序页下载握手指令报文字节7";
CM_ SG_ 2149220180 P2D_DLoadInfo_Data0 "发送的flash程序页下载握手指令报文字节0";
CM_ SG_ 2149220180 P2D_DLoadInfo_Data1 "发送的flash程序页下载握手指令报文字节1";
CM_ SG_ 2149220180 P2D_DLoadInfo_Data2 "发送的flash程序页下载握手指令报文字节2";
CM_ SG_ 2149220180 P2D_DLoadInfo_Data3 "发送的flash程序页下载握手指令报文字节3";
CM_ SG_ 2149220180 P2D_DLoadInfo_Data4 "发送的flash程序页下载握手指令报文字节4";
CM_ SG_ 2149220180 P2D_DLoadInfo_Data5 "发送的flash程序页下载握手指令报文字节5";
CM_ SG_ 2149220180 P2D_DLoadInfo_Data6 "发送的flash程序页下载握手指令报文字节6";
CM_ SG_ 2149220180 P2D_DLoadInfo_Data7 "发送的flash程序页下载握手指令报文字节7";
CM_ SG_ 2149220181 P2D_DLoadInfo_Data0 "发送的flash程序页下载握手指令报文字节0";
CM_ SG_ 2149220181 P2D_DLoadInfo_Data1 "发送的flash程序页下载握手指令报文字节1";
CM_ SG_ 2149220181 P2D_DLoadInfo_Data2 "发送的flash程序页下载握手指令报文字节2";
CM_ SG_ 2149220181 P2D_DLoadInfo_Data3 "发送的flash程序页下载握手指令报文字节3";
CM_ SG_ 2149220181 P2D_DLoadInfo_Data4 "发送的flash程序页下载握手指令报文字节4";
CM_ SG_ 2149220181 P2D_DLoadInfo_Data5 "发送的flash程序页下载握手指令报文字节5";
CM_ SG_ 2149220181 P2D_DLoadInfo_Data6 "发送的flash程序页下载握手指令报文字节6";
CM_ SG_ 2149220181 P2D_DLoadInfo_Data7 "发送的flash程序页下载握手指令报文字节7";
CM_ SG_ 2149220182 P2D_DLoadInfo_Data0 "发送的flash程序页下载握手指令报文字节0";
CM_ SG_ 2149220182 P2D_DLoadInfo_Data1 "发送的flash程序页下载握手指令报文字节1";
CM_ SG_ 2149220182 P2D_DLoadInfo_Data2 "发送的flash程序页下载握手指令报文字节2";
CM_ SG_ 2149220182 P2D_DLoadInfo_Data3 "发送的flash程序页下载握手指令报文字节3";
CM_ SG_ 2149220182 P2D_DLoadInfo_Data4 "发送的flash程序页下载握手指令报文字节4";
CM_ SG_ 2149220182 P2D_DLoadInfo_Data5 "发送的flash程序页下载握手指令报文字节5";
CM_ SG_ 2149220182 P2D_DLoadInfo_Data6 "发送的flash程序页下载握手指令报文字节6";
CM_ SG_ 2149220182 P2D_DLoadInfo_Data7 "发送的flash程序页下载握手指令报文字节7";
CM_ SG_ 2149220183 P2D_DLoadInfo_Data0 "发送的flash程序页下载握手指令报文字节0";
CM_ SG_ 2149220183 P2D_DLoadInfo_Data1 "发送的flash程序页下载握手指令报文字节1";
CM_ SG_ 2149220183 P2D_DLoadInfo_Data2 "发送的flash程序页下载握手指令报文字节2";
CM_ SG_ 2149220183 P2D_DLoadInfo_Data3 "发送的flash程序页下载握手指令报文字节3";
CM_ SG_ 2149220183 P2D_DLoadInfo_Data4 "发送的flash程序页下载握手指令报文字节4";
CM_ SG_ 2149220183 P2D_DLoadInfo_Data5 "发送的flash程序页下载握手指令报文字节5";
CM_ SG_ 2149220183 P2D_DLoadInfo_Data6 "发送的flash程序页下载握手指令报文字节6";
CM_ SG_ 2149220183 P2D_DLoadInfo_Data7 "发送的flash程序页下载握手指令报文字节7";
CM_ SG_ 2149220184 P2D_DLoadInfo_Data0 "发送的flash程序页下载握手指令报文字节0";
CM_ SG_ 2149220184 P2D_DLoadInfo_Data1 "发送的flash程序页下载握手指令报文字节1";
CM_ SG_ 2149220184 P2D_DLoadInfo_Data2 "发送的flash程序页下载握手指令报文字节2";
CM_ SG_ 2149220184 P2D_DLoadInfo_Data3 "发送的flash程序页下载握手指令报文字节3";
CM_ SG_ 2149220184 P2D_DLoadInfo_Data4 "发送的flash程序页下载握手指令报文字节4";
CM_ SG_ 2149220184 P2D_DLoadInfo_Data5 "发送的flash程序页下载握手指令报文字节5";
CM_ SG_ 2149220184 P2D_DLoadInfo_Data6 "发送的flash程序页下载握手指令报文字节6";
CM_ SG_ 2149220184 P2D_DLoadInfo_Data7 "发送的flash程序页下载握手指令报文字节7";
CM_ SG_ 2149220185 P2D_DLoadInfo_Data0 "发送的flash程序页下载握手指令报文字节0";
CM_ SG_ 2149220185 P2D_DLoadInfo_Data1 "发送的flash程序页下载握手指令报文字节1";
CM_ SG_ 2149220185 P2D_DLoadInfo_Data2 "发送的flash程序页下载握手指令报文字节2";
CM_ SG_ 2149220185 P2D_DLoadInfo_Data3 "发送的flash程序页下载握手指令报文字节3";
CM_ SG_ 2149220185 P2D_DLoadInfo_Data4 "发送的flash程序页下载握手指令报文字节4";
CM_ SG_ 2149220185 P2D_DLoadInfo_Data5 "发送的flash程序页下载握手指令报文字节5";
CM_ SG_ 2149220185 P2D_DLoadInfo_Data6 "发送的flash程序页下载握手指令报文字节6";
CM_ SG_ 2149220185 P2D_DLoadInfo_Data7 "发送的flash程序页下载握手指令报文字节7";
CM_ SG_ 2149220186 P2D_DLoadInfo_Data0 "发送的flash程序页下载握手指令报文字节0";
CM_ SG_ 2149220186 P2D_DLoadInfo_Data1 "发送的flash程序页下载握手指令报文字节1";
CM_ SG_ 2149220186 P2D_DLoadInfo_Data2 "发送的flash程序页下载握手指令报文字节2";
CM_ SG_ 2149220186 P2D_DLoadInfo_Data3 "发送的flash程序页下载握手指令报文字节3";
CM_ SG_ 2149220186 P2D_DLoadInfo_Data4 "发送的flash程序页下载握手指令报文字节4";
CM_ SG_ 2149220186 P2D_DLoadInfo_Data5 "发送的flash程序页下载握手指令报文字节5";
CM_ SG_ 2149220186 P2D_DLoadInfo_Data6 "发送的flash程序页下载握手指令报文字节6";
CM_ SG_ 2149220186 P2D_DLoadInfo_Data7 "发送的flash程序页下载握手指令报文字节7";
CM_ SG_ 2149220187 P2D_DLoadInfo_Data0 "发送的flash程序页下载握手指令报文字节0";
CM_ SG_ 2149220187 P2D_DLoadInfo_Data1 "发送的flash程序页下载握手指令报文字节1";
CM_ SG_ 2149220187 P2D_DLoadInfo_Data2 "发送的flash程序页下载握手指令报文字节2";
CM_ SG_ 2149220187 P2D_DLoadInfo_Data3 "发送的flash程序页下载握手指令报文字节3";
CM_ SG_ 2149220187 P2D_DLoadInfo_Data4 "发送的flash程序页下载握手指令报文字节4";
CM_ SG_ 2149220187 P2D_DLoadInfo_Data5 "发送的flash程序页下载握手指令报文字节5";
CM_ SG_ 2149220187 P2D_DLoadInfo_Data6 "发送的flash程序页下载握手指令报文字节6";
CM_ SG_ 2149220187 P2D_DLoadInfo_Data7 "发送的flash程序页下载握手指令报文字节7";
CM_ SG_ 2149220188 P2D_DLoadInfo_Data0 "发送的flash程序页下载握手指令报文字节0";
CM_ SG_ 2149220188 P2D_DLoadInfo_Data1 "发送的flash程序页下载握手指令报文字节1";
CM_ SG_ 2149220188 P2D_DLoadInfo_Data2 "发送的flash程序页下载握手指令报文字节2";
CM_ SG_ 2149220188 P2D_DLoadInfo_Data3 "发送的flash程序页下载握手指令报文字节3";
CM_ SG_ 2149220188 P2D_DLoadInfo_Data4 "发送的flash程序页下载握手指令报文字节4";
CM_ SG_ 2149220188 P2D_DLoadInfo_Data5 "发送的flash程序页下载握手指令报文字节5";
CM_ SG_ 2149220188 P2D_DLoadInfo_Data6 "发送的flash程序页下载握手指令报文字节6";
CM_ SG_ 2149220188 P2D_DLoadInfo_Data7 "发送的flash程序页下载握手指令报文字节7";
CM_ SG_ 2149220189 P2D_DLoadInfo_Data0 "发送的flash程序页下载握手指令报文字节0";
CM_ SG_ 2149220189 P2D_DLoadInfo_Data1 "发送的flash程序页下载握手指令报文字节1";
CM_ SG_ 2149220189 P2D_DLoadInfo_Data2 "发送的flash程序页下载握手指令报文字节2";
CM_ SG_ 2149220189 P2D_DLoadInfo_Data3 "发送的flash程序页下载握手指令报文字节3";
CM_ SG_ 2149220189 P2D_DLoadInfo_Data4 "发送的flash程序页下载握手指令报文字节4";
CM_ SG_ 2149220189 P2D_DLoadInfo_Data5 "发送的flash程序页下载握手指令报文字节5";
CM_ SG_ 2149220189 P2D_DLoadInfo_Data6 "发送的flash程序页下载握手指令报文字节6";
CM_ SG_ 2149220189 P2D_DLoadInfo_Data7 "发送的flash程序页下载握手指令报文字节7";
CM_ SG_ 2149220190 P2D_DLoadInfo_Data0 "发送的flash程序页下载握手指令报文字节0";
CM_ SG_ 2149220190 P2D_DLoadInfo_Data1 "发送的flash程序页下载握手指令报文字节1";
CM_ SG_ 2149220190 P2D_DLoadInfo_Data2 "发送的flash程序页下载握手指令报文字节2";
CM_ SG_ 2149220190 P2D_DLoadInfo_Data3 "发送的flash程序页下载握手指令报文字节3";
CM_ SG_ 2149220190 P2D_DLoadInfo_Data4 "发送的flash程序页下载握手指令报文字节4";
CM_ SG_ 2149220190 P2D_DLoadInfo_Data5 "发送的flash程序页下载握手指令报文字节5";
CM_ SG_ 2149220190 P2D_DLoadInfo_Data6 "发送的flash程序页下载握手指令报文字节6";
CM_ SG_ 2149220190 P2D_DLoadInfo_Data7 "发送的flash程序页下载握手指令报文字节7";
CM_ SG_ 2149220191 P2D_DLoadInfo_Data0 "发送的flash程序页下载握手指令报文字节0";
CM_ SG_ 2149220191 P2D_DLoadInfo_Data1 "发送的flash程序页下载握手指令报文字节1";
CM_ SG_ 2149220191 P2D_DLoadInfo_Data2 "发送的flash程序页下载握手指令报文字节2";
CM_ SG_ 2149220191 P2D_DLoadInfo_Data3 "发送的flash程序页下载握手指令报文字节3";
CM_ SG_ 2149220191 P2D_DLoadInfo_Data4 "发送的flash程序页下载握手指令报文字节4";
CM_ SG_ 2149220191 P2D_DLoadInfo_Data5 "发送的flash程序页下载握手指令报文字节5";
CM_ SG_ 2149220191 P2D_DLoadInfo_Data6 "发送的flash程序页下载握手指令报文字节6";
CM_ SG_ 2149220191 P2D_DLoadInfo_Data7 "发送的flash程序页下载握手指令报文字节7";
CM_ SG_ 2149220192 P2D_DLoadInfo_Data0 "发送的flash程序页下载握手指令报文字节0";
CM_ SG_ 2149220192 P2D_DLoadInfo_Data1 "发送的flash程序页下载握手指令报文字节1";
CM_ SG_ 2149220192 P2D_DLoadInfo_Data2 "发送的flash程序页下载握手指令报文字节2";
CM_ SG_ 2149220192 P2D_DLoadInfo_Data3 "发送的flash程序页下载握手指令报文字节3";
CM_ SG_ 2149220192 P2D_DLoadInfo_Data4 "发送的flash程序页下载握手指令报文字节4";
CM_ SG_ 2149220192 P2D_DLoadInfo_Data5 "发送的flash程序页下载握手指令报文字节5";
CM_ SG_ 2149220192 P2D_DLoadInfo_Data6 "发送的flash程序页下载握手指令报文字节6";
CM_ SG_ 2149220192 P2D_DLoadInfo_Data7 "发送的flash程序页下载握手指令报文字节7";
CM_ SG_ 2149220193 P2D_DLoadInfo_Data0 "发送的flash程序页下载握手指令报文字节0";
CM_ SG_ 2149220193 P2D_DLoadInfo_Data1 "发送的flash程序页下载握手指令报文字节1";
CM_ SG_ 2149220193 P2D_DLoadInfo_Data2 "发送的flash程序页下载握手指令报文字节2";
CM_ SG_ 2149220193 P2D_DLoadInfo_Data3 "发送的flash程序页下载握手指令报文字节3";
CM_ SG_ 2149220193 P2D_DLoadInfo_Data4 "发送的flash程序页下载握手指令报文字节4";
CM_ SG_ 2149220193 P2D_DLoadInfo_Data5 "发送的flash程序页下载握手指令报文字节5";
CM_ SG_ 2149220193 P2D_DLoadInfo_Data6 "发送的flash程序页下载握手指令报文字节6";
CM_ SG_ 2149220193 P2D_DLoadInfo_Data7 "发送的flash程序页下载握手指令报文字节7";
CM_ SG_ 2149220194 P2D_DLoadInfo_Data0 "发送的flash程序页下载握手指令报文字节0";
CM_ SG_ 2149220194 P2D_DLoadInfo_Data1 "发送的flash程序页下载握手指令报文字节1";
CM_ SG_ 2149220194 P2D_DLoadInfo_Data2 "发送的flash程序页下载握手指令报文字节2";
CM_ SG_ 2149220194 P2D_DLoadInfo_Data3 "发送的flash程序页下载握手指令报文字节3";
CM_ SG_ 2149220194 P2D_DLoadInfo_Data4 "发送的flash程序页下载握手指令报文字节4";
CM_ SG_ 2149220194 P2D_DLoadInfo_Data5 "发送的flash程序页下载握手指令报文字节5";
CM_ SG_ 2149220194 P2D_DLoadInfo_Data6 "发送的flash程序页下载握手指令报文字节6";
CM_ SG_ 2149220194 P2D_DLoadInfo_Data7 "发送的flash程序页下载握手指令报文字节7";
CM_ SG_ 2149220195 P2D_DLoadInfo_Data0 "发送的flash程序页下载握手指令报文字节0";
CM_ SG_ 2149220195 P2D_DLoadInfo_Data1 "发送的flash程序页下载握手指令报文字节1";
CM_ SG_ 2149220195 P2D_DLoadInfo_Data2 "发送的flash程序页下载握手指令报文字节2";
CM_ SG_ 2149220195 P2D_DLoadInfo_Data3 "发送的flash程序页下载握手指令报文字节3";
CM_ SG_ 2149220195 P2D_DLoadInfo_Data4 "发送的flash程序页下载握手指令报文字节4";
CM_ SG_ 2149220195 P2D_DLoadInfo_Data5 "发送的flash程序页下载握手指令报文字节5";
CM_ SG_ 2149220195 P2D_DLoadInfo_Data6 "发送的flash程序页下载握手指令报文字节6";
CM_ SG_ 2149220195 P2D_DLoadInfo_Data7 "发送的flash程序页下载握手指令报文字节7";
CM_ SG_ 2149220196 P2D_DLoadInfo_Data0 "发送的flash程序页下载握手指令报文字节0";
CM_ SG_ 2149220196 P2D_DLoadInfo_Data1 "发送的flash程序页下载握手指令报文字节1";
CM_ SG_ 2149220196 P2D_DLoadInfo_Data2 "发送的flash程序页下载握手指令报文字节2";
CM_ SG_ 2149220196 P2D_DLoadInfo_Data3 "发送的flash程序页下载握手指令报文字节3";
CM_ SG_ 2149220196 P2D_DLoadInfo_Data4 "发送的flash程序页下载握手指令报文字节4";
CM_ SG_ 2149220196 P2D_DLoadInfo_Data5 "发送的flash程序页下载握手指令报文字节5";
CM_ SG_ 2149220196 P2D_DLoadInfo_Data6 "发送的flash程序页下载握手指令报文字节6";
CM_ SG_ 2149220196 P2D_DLoadInfo_Data7 "发送的flash程序页下载握手指令报文字节7";
CM_ SG_ 2149220197 P2D_DLoadInfo_Data0 "发送的flash程序页下载握手指令报文字节0";
CM_ SG_ 2149220197 P2D_DLoadInfo_Data1 "发送的flash程序页下载握手指令报文字节1";
CM_ SG_ 2149220197 P2D_DLoadInfo_Data2 "发送的flash程序页下载握手指令报文字节2";
CM_ SG_ 2149220197 P2D_DLoadInfo_Data3 "发送的flash程序页下载握手指令报文字节3";
CM_ SG_ 2149220197 P2D_DLoadInfo_Data4 "发送的flash程序页下载握手指令报文字节4";
CM_ SG_ 2149220197 P2D_DLoadInfo_Data5 "发送的flash程序页下载握手指令报文字节5";
CM_ SG_ 2149220197 P2D_DLoadInfo_Data6 "发送的flash程序页下载握手指令报文字节6";
CM_ SG_ 2149220197 P2D_DLoadInfo_Data7 "发送的flash程序页下载握手指令报文字节7";
CM_ SG_ 2149220198 P2D_DLoadInfo_Data0 "发送的flash程序页下载握手指令报文字节0";
CM_ SG_ 2149220198 P2D_DLoadInfo_Data1 "发送的flash程序页下载握手指令报文字节1";
CM_ SG_ 2149220198 P2D_DLoadInfo_Data2 "发送的flash程序页下载握手指令报文字节2";
CM_ SG_ 2149220198 P2D_DLoadInfo_Data3 "发送的flash程序页下载握手指令报文字节3";
CM_ SG_ 2149220198 P2D_DLoadInfo_Data4 "发送的flash程序页下载握手指令报文字节4";
CM_ SG_ 2149220198 P2D_DLoadInfo_Data5 "发送的flash程序页下载握手指令报文字节5";
CM_ SG_ 2149220198 P2D_DLoadInfo_Data6 "发送的flash程序页下载握手指令报文字节6";
CM_ SG_ 2149220198 P2D_DLoadInfo_Data7 "发送的flash程序页下载握手指令报文字节7";
CM_ SG_ 2149220199 P2D_DLoadInfo_Data0 "发送的flash程序页下载握手指令报文字节0";
CM_ SG_ 2149220199 P2D_DLoadInfo_Data1 "发送的flash程序页下载握手指令报文字节1";
CM_ SG_ 2149220199 P2D_DLoadInfo_Data2 "发送的flash程序页下载握手指令报文字节2";
CM_ SG_ 2149220199 P2D_DLoadInfo_Data3 "发送的flash程序页下载握手指令报文字节3";
CM_ SG_ 2149220199 P2D_DLoadInfo_Data4 "发送的flash程序页下载握手指令报文字节4";
CM_ SG_ 2149220199 P2D_DLoadInfo_Data5 "发送的flash程序页下载握手指令报文字节5";
CM_ SG_ 2149220199 P2D_DLoadInfo_Data6 "发送的flash程序页下载握手指令报文字节6";
CM_ SG_ 2149220199 P2D_DLoadInfo_Data7 "发送的flash程序页下载握手指令报文字节7";
CM_ SG_ 2149220200 P2D_DLoadInfo_Data0 "发送的flash程序页下载握手指令报文字节0";
CM_ SG_ 2149220200 P2D_DLoadInfo_Data1 "发送的flash程序页下载握手指令报文字节1";
CM_ SG_ 2149220200 P2D_DLoadInfo_Data2 "发送的flash程序页下载握手指令报文字节2";
CM_ SG_ 2149220200 P2D_DLoadInfo_Data3 "发送的flash程序页下载握手指令报文字节3";
CM_ SG_ 2149220200 P2D_DLoadInfo_Data4 "发送的flash程序页下载握手指令报文字节4";
CM_ SG_ 2149220200 P2D_DLoadInfo_Data5 "发送的flash程序页下载握手指令报文字节5";
CM_ SG_ 2149220200 P2D_DLoadInfo_Data6 "发送的flash程序页下载握手指令报文字节6";
CM_ SG_ 2149220200 P2D_DLoadInfo_Data7 "发送的flash程序页下载握手指令报文字节7";
CM_ SG_ 2149220201 P2D_DLoadInfo_Data0 "发送的flash程序页下载握手指令报文字节0";
CM_ SG_ 2149220201 P2D_DLoadInfo_Data1 "发送的flash程序页下载握手指令报文字节1";
CM_ SG_ 2149220201 P2D_DLoadInfo_Data2 "发送的flash程序页下载握手指令报文字节2";
CM_ SG_ 2149220201 P2D_DLoadInfo_Data3 "发送的flash程序页下载握手指令报文字节3";
CM_ SG_ 2149220201 P2D_DLoadInfo_Data4 "发送的flash程序页下载握手指令报文字节4";
CM_ SG_ 2149220201 P2D_DLoadInfo_Data5 "发送的flash程序页下载握手指令报文字节5";
CM_ SG_ 2149220201 P2D_DLoadInfo_Data6 "发送的flash程序页下载握手指令报文字节6";
CM_ SG_ 2149220201 P2D_DLoadInfo_Data7 "发送的flash程序页下载握手指令报文字节7";
CM_ SG_ 2149220202 P2D_DLoadInfo_Data0 "发送的flash程序页下载握手指令报文字节0";
CM_ SG_ 2149220202 P2D_DLoadInfo_Data1 "发送的flash程序页下载握手指令报文字节1";
CM_ SG_ 2149220202 P2D_DLoadInfo_Data2 "发送的flash程序页下载握手指令报文字节2";
CM_ SG_ 2149220202 P2D_DLoadInfo_Data3 "发送的flash程序页下载握手指令报文字节3";
CM_ SG_ 2149220202 P2D_DLoadInfo_Data4 "发送的flash程序页下载握手指令报文字节4";
CM_ SG_ 2149220202 P2D_DLoadInfo_Data5 "发送的flash程序页下载握手指令报文字节5";
CM_ SG_ 2149220202 P2D_DLoadInfo_Data6 "发送的flash程序页下载握手指令报文字节6";
CM_ SG_ 2149220202 P2D_DLoadInfo_Data7 "发送的flash程序页下载握手指令报文字节7";
CM_ SG_ 2149220203 P2D_DLoadInfo_Data0 "发送的flash程序页下载握手指令报文字节0";
CM_ SG_ 2149220203 P2D_DLoadInfo_Data1 "发送的flash程序页下载握手指令报文字节1";
CM_ SG_ 2149220203 P2D_DLoadInfo_Data2 "发送的flash程序页下载握手指令报文字节2";
CM_ SG_ 2149220203 P2D_DLoadInfo_Data3 "发送的flash程序页下载握手指令报文字节3";
CM_ SG_ 2149220203 P2D_DLoadInfo_Data4 "发送的flash程序页下载握手指令报文字节4";
CM_ SG_ 2149220203 P2D_DLoadInfo_Data5 "发送的flash程序页下载握手指令报文字节5";
CM_ SG_ 2149220203 P2D_DLoadInfo_Data6 "发送的flash程序页下载握手指令报文字节6";
CM_ SG_ 2149220203 P2D_DLoadInfo_Data7 "发送的flash程序页下载握手指令报文字节7";
CM_ SG_ 2149220204 P2D_DLoadInfo_Data0 "发送的flash程序页下载握手指令报文字节0";
CM_ SG_ 2149220204 P2D_DLoadInfo_Data1 "发送的flash程序页下载握手指令报文字节1";
CM_ SG_ 2149220204 P2D_DLoadInfo_Data2 "发送的flash程序页下载握手指令报文字节2";
CM_ SG_ 2149220204 P2D_DLoadInfo_Data3 "发送的flash程序页下载握手指令报文字节3";
CM_ SG_ 2149220204 P2D_DLoadInfo_Data4 "发送的flash程序页下载握手指令报文字节4";
CM_ SG_ 2149220204 P2D_DLoadInfo_Data5 "发送的flash程序页下载握手指令报文字节5";
CM_ SG_ 2149220204 P2D_DLoadInfo_Data6 "发送的flash程序页下载握手指令报文字节6";
CM_ SG_ 2149220204 P2D_DLoadInfo_Data7 "发送的flash程序页下载握手指令报文字节7";
CM_ SG_ 2149220205 P2D_DLoadInfo_Data0 "发送的flash程序页下载握手指令报文字节0";
CM_ SG_ 2149220205 P2D_DLoadInfo_Data1 "发送的flash程序页下载握手指令报文字节1";
CM_ SG_ 2149220205 P2D_DLoadInfo_Data2 "发送的flash程序页下载握手指令报文字节2";
CM_ SG_ 2149220205 P2D_DLoadInfo_Data3 "发送的flash程序页下载握手指令报文字节3";
CM_ SG_ 2149220205 P2D_DLoadInfo_Data4 "发送的flash程序页下载握手指令报文字节4";
CM_ SG_ 2149220205 P2D_DLoadInfo_Data5 "发送的flash程序页下载握手指令报文字节5";
CM_ SG_ 2149220205 P2D_DLoadInfo_Data6 "发送的flash程序页下载握手指令报文字节6";
CM_ SG_ 2149220205 P2D_DLoadInfo_Data7 "发送的flash程序页下载握手指令报文字节7";
CM_ SG_ 2149220206 P2D_DLoadInfo_Data0 "发送的flash程序页下载握手指令报文字节0";
CM_ SG_ 2149220206 P2D_DLoadInfo_Data1 "发送的flash程序页下载握手指令报文字节1";
CM_ SG_ 2149220206 P2D_DLoadInfo_Data2 "发送的flash程序页下载握手指令报文字节2";
CM_ SG_ 2149220206 P2D_DLoadInfo_Data3 "发送的flash程序页下载握手指令报文字节3";
CM_ SG_ 2149220206 P2D_DLoadInfo_Data4 "发送的flash程序页下载握手指令报文字节4";
CM_ SG_ 2149220206 P2D_DLoadInfo_Data5 "发送的flash程序页下载握手指令报文字节5";
CM_ SG_ 2149220206 P2D_DLoadInfo_Data6 "发送的flash程序页下载握手指令报文字节6";
CM_ SG_ 2149220206 P2D_DLoadInfo_Data7 "发送的flash程序页下载握手指令报文字节7";
CM_ SG_ 2149220207 P2D_DLoadInfo_Data0 "发送的flash程序页下载握手指令报文字节0";
CM_ SG_ 2149220207 P2D_DLoadInfo_Data1 "发送的flash程序页下载握手指令报文字节1";
CM_ SG_ 2149220207 P2D_DLoadInfo_Data2 "发送的flash程序页下载握手指令报文字节2";
CM_ SG_ 2149220207 P2D_DLoadInfo_Data3 "发送的flash程序页下载握手指令报文字节3";
CM_ SG_ 2149220207 P2D_DLoadInfo_Data4 "发送的flash程序页下载握手指令报文字节4";
CM_ SG_ 2149220207 P2D_DLoadInfo_Data5 "发送的flash程序页下载握手指令报文字节5";
CM_ SG_ 2149220207 P2D_DLoadInfo_Data6 "发送的flash程序页下载握手指令报文字节6";
CM_ SG_ 2149220207 P2D_DLoadInfo_Data7 "发送的flash程序页下载握手指令报文字节7";
CM_ SG_ 2149220208 P2D_DLoadInfo_Data0 "发送的flash程序页下载握手指令报文字节0";
CM_ SG_ 2149220208 P2D_DLoadInfo_Data1 "发送的flash程序页下载握手指令报文字节1";
CM_ SG_ 2149220208 P2D_DLoadInfo_Data2 "发送的flash程序页下载握手指令报文字节2";
CM_ SG_ 2149220208 P2D_DLoadInfo_Data3 "发送的flash程序页下载握手指令报文字节3";
CM_ SG_ 2149220208 P2D_DLoadInfo_Data4 "发送的flash程序页下载握手指令报文字节4";
CM_ SG_ 2149220208 P2D_DLoadInfo_Data5 "发送的flash程序页下载握手指令报文字节5";
CM_ SG_ 2149220208 P2D_DLoadInfo_Data6 "发送的flash程序页下载握手指令报文字节6";
CM_ SG_ 2149220208 P2D_DLoadInfo_Data7 "发送的flash程序页下载握手指令报文字节7";
CM_ SG_ 2149220209 P2D_DLoadInfo_Data0 "发送的flash程序页下载握手指令报文字节0";
CM_ SG_ 2149220209 P2D_DLoadInfo_Data1 "发送的flash程序页下载握手指令报文字节1";
CM_ SG_ 2149220209 P2D_DLoadInfo_Data2 "发送的flash程序页下载握手指令报文字节2";
CM_ SG_ 2149220209 P2D_DLoadInfo_Data3 "发送的flash程序页下载握手指令报文字节3";
CM_ SG_ 2149220209 P2D_DLoadInfo_Data4 "发送的flash程序页下载握手指令报文字节4";
CM_ SG_ 2149220209 P2D_DLoadInfo_Data5 "发送的flash程序页下载握手指令报文字节5";
CM_ SG_ 2149220209 P2D_DLoadInfo_Data6 "发送的flash程序页下载握手指令报文字节6";
CM_ SG_ 2149220209 P2D_DLoadInfo_Data7 "发送的flash程序页下载握手指令报文字节7";
CM_ SG_ 2149220210 P2D_DLoadInfo_Data0 "发送的flash程序页下载握手指令报文字节0";
CM_ SG_ 2149220210 P2D_DLoadInfo_Data1 "发送的flash程序页下载握手指令报文字节1";
CM_ SG_ 2149220210 P2D_DLoadInfo_Data2 "发送的flash程序页下载握手指令报文字节2";
CM_ SG_ 2149220210 P2D_DLoadInfo_Data3 "发送的flash程序页下载握手指令报文字节3";
CM_ SG_ 2149220210 P2D_DLoadInfo_Data4 "发送的flash程序页下载握手指令报文字节4";
CM_ SG_ 2149220210 P2D_DLoadInfo_Data5 "发送的flash程序页下载握手指令报文字节5";
CM_ SG_ 2149220210 P2D_DLoadInfo_Data6 "发送的flash程序页下载握手指令报文字节6";
CM_ SG_ 2149220210 P2D_DLoadInfo_Data7 "发送的flash程序页下载握手指令报文字节7";
CM_ SG_ 2149220211 P2D_DLoadInfo_Data0 "发送的flash程序页下载握手指令报文字节0";
CM_ SG_ 2149220211 P2D_DLoadInfo_Data1 "发送的flash程序页下载握手指令报文字节1";
CM_ SG_ 2149220211 P2D_DLoadInfo_Data2 "发送的flash程序页下载握手指令报文字节2";
CM_ SG_ 2149220211 P2D_DLoadInfo_Data3 "发送的flash程序页下载握手指令报文字节3";
CM_ SG_ 2149220211 P2D_DLoadInfo_Data4 "发送的flash程序页下载握手指令报文字节4";
CM_ SG_ 2149220211 P2D_DLoadInfo_Data5 "发送的flash程序页下载握手指令报文字节5";
CM_ SG_ 2149220211 P2D_DLoadInfo_Data6 "发送的flash程序页下载握手指令报文字节6";
CM_ SG_ 2149220211 P2D_DLoadInfo_Data7 "发送的flash程序页下载握手指令报文字节7";
CM_ SG_ 2149220212 P2D_DLoadInfo_Data0 "发送的flash程序页下载握手指令报文字节0";
CM_ SG_ 2149220212 P2D_DLoadInfo_Data1 "发送的flash程序页下载握手指令报文字节1";
CM_ SG_ 2149220212 P2D_DLoadInfo_Data2 "发送的flash程序页下载握手指令报文字节2";
CM_ SG_ 2149220212 P2D_DLoadInfo_Data3 "发送的flash程序页下载握手指令报文字节3";
CM_ SG_ 2149220212 P2D_DLoadInfo_Data4 "发送的flash程序页下载握手指令报文字节4";
CM_ SG_ 2149220212 P2D_DLoadInfo_Data5 "发送的flash程序页下载握手指令报文字节5";
CM_ SG_ 2149220212 P2D_DLoadInfo_Data6 "发送的flash程序页下载握手指令报文字节6";
CM_ SG_ 2149220212 P2D_DLoadInfo_Data7 "发送的flash程序页下载握手指令报文字节7";
CM_ SG_ 2149220213 P2D_DLoadInfo_Data0 "发送的flash程序页下载握手指令报文字节0";
CM_ SG_ 2149220213 P2D_DLoadInfo_Data1 "发送的flash程序页下载握手指令报文字节1";
CM_ SG_ 2149220213 P2D_DLoadInfo_Data2 "发送的flash程序页下载握手指令报文字节2";
CM_ SG_ 2149220213 P2D_DLoadInfo_Data3 "发送的flash程序页下载握手指令报文字节3";
CM_ SG_ 2149220213 P2D_DLoadInfo_Data4 "发送的flash程序页下载握手指令报文字节4";
CM_ SG_ 2149220213 P2D_DLoadInfo_Data5 "发送的flash程序页下载握手指令报文字节5";
CM_ SG_ 2149220213 P2D_DLoadInfo_Data6 "发送的flash程序页下载握手指令报文字节6";
CM_ SG_ 2149220213 P2D_DLoadInfo_Data7 "发送的flash程序页下载握手指令报文字节7";
CM_ SG_ 2149220214 P2D_DLoadInfo_Data0 "发送的flash程序页下载握手指令报文字节0";
CM_ SG_ 2149220214 P2D_DLoadInfo_Data1 "发送的flash程序页下载握手指令报文字节1";
CM_ SG_ 2149220214 P2D_DLoadInfo_Data2 "发送的flash程序页下载握手指令报文字节2";
CM_ SG_ 2149220214 P2D_DLoadInfo_Data3 "发送的flash程序页下载握手指令报文字节3";
CM_ SG_ 2149220214 P2D_DLoadInfo_Data4 "发送的flash程序页下载握手指令报文字节4";
CM_ SG_ 2149220214 P2D_DLoadInfo_Data5 "发送的flash程序页下载握手指令报文字节5";
CM_ SG_ 2149220214 P2D_DLoadInfo_Data6 "发送的flash程序页下载握手指令报文字节6";
CM_ SG_ 2149220214 P2D_DLoadInfo_Data7 "发送的flash程序页下载握手指令报文字节7";
CM_ SG_ 2149220215 P2D_DLoadInfo_Data0 "发送的flash程序页下载握手指令报文字节0";
CM_ SG_ 2149220215 P2D_DLoadInfo_Data1 "发送的flash程序页下载握手指令报文字节1";
CM_ SG_ 2149220215 P2D_DLoadInfo_Data2 "发送的flash程序页下载握手指令报文字节2";
CM_ SG_ 2149220215 P2D_DLoadInfo_Data3 "发送的flash程序页下载握手指令报文字节3";
CM_ SG_ 2149220215 P2D_DLoadInfo_Data4 "发送的flash程序页下载握手指令报文字节4";
CM_ SG_ 2149220215 P2D_DLoadInfo_Data5 "发送的flash程序页下载握手指令报文字节5";
CM_ SG_ 2149220215 P2D_DLoadInfo_Data6 "发送的flash程序页下载握手指令报文字节6";
CM_ SG_ 2149220215 P2D_DLoadInfo_Data7 "发送的flash程序页下载握手指令报文字节7";
CM_ SG_ 2149220216 P2D_DLoadInfo_Data0 "发送的flash程序页下载握手指令报文字节0";
CM_ SG_ 2149220216 P2D_DLoadInfo_Data1 "发送的flash程序页下载握手指令报文字节1";
CM_ SG_ 2149220216 P2D_DLoadInfo_Data2 "发送的flash程序页下载握手指令报文字节2";
CM_ SG_ 2149220216 P2D_DLoadInfo_Data3 "发送的flash程序页下载握手指令报文字节3";
CM_ SG_ 2149220216 P2D_DLoadInfo_Data4 "发送的flash程序页下载握手指令报文字节4";
CM_ SG_ 2149220216 P2D_DLoadInfo_Data5 "发送的flash程序页下载握手指令报文字节5";
CM_ SG_ 2149220216 P2D_DLoadInfo_Data6 "发送的flash程序页下载握手指令报文字节6";
CM_ SG_ 2149220216 P2D_DLoadInfo_Data7 "发送的flash程序页下载握手指令报文字节7";
CM_ SG_ 2149220217 P2D_DLoadInfo_Data0 "发送的flash程序页下载握手指令报文字节0";
CM_ SG_ 2149220217 P2D_DLoadInfo_Data1 "发送的flash程序页下载握手指令报文字节1";
CM_ SG_ 2149220217 P2D_DLoadInfo_Data2 "发送的flash程序页下载握手指令报文字节2";
CM_ SG_ 2149220217 P2D_DLoadInfo_Data3 "发送的flash程序页下载握手指令报文字节3";
CM_ SG_ 2149220217 P2D_DLoadInfo_Data4 "发送的flash程序页下载握手指令报文字节4";
CM_ SG_ 2149220217 P2D_DLoadInfo_Data5 "发送的flash程序页下载握手指令报文字节5";
CM_ SG_ 2149220217 P2D_DLoadInfo_Data6 "发送的flash程序页下载握手指令报文字节6";
CM_ SG_ 2149220217 P2D_DLoadInfo_Data7 "发送的flash程序页下载握手指令报文字节7";
CM_ SG_ 2149220218 P2D_DLoadInfo_Data0 "发送的flash程序页下载握手指令报文字节0";
CM_ SG_ 2149220218 P2D_DLoadInfo_Data1 "发送的flash程序页下载握手指令报文字节1";
CM_ SG_ 2149220218 P2D_DLoadInfo_Data2 "发送的flash程序页下载握手指令报文字节2";
CM_ SG_ 2149220218 P2D_DLoadInfo_Data3 "发送的flash程序页下载握手指令报文字节3";
CM_ SG_ 2149220218 P2D_DLoadInfo_Data4 "发送的flash程序页下载握手指令报文字节4";
CM_ SG_ 2149220218 P2D_DLoadInfo_Data5 "发送的flash程序页下载握手指令报文字节5";
CM_ SG_ 2149220218 P2D_DLoadInfo_Data6 "发送的flash程序页下载握手指令报文字节6";
CM_ SG_ 2149220218 P2D_DLoadInfo_Data7 "发送的flash程序页下载握手指令报文字节7";
CM_ SG_ 2149220219 P2D_DLoadInfo_Data0 "发送的flash程序页下载握手指令报文字节0";
CM_ SG_ 2149220219 P2D_DLoadInfo_Data1 "发送的flash程序页下载握手指令报文字节1";
CM_ SG_ 2149220219 P2D_DLoadInfo_Data2 "发送的flash程序页下载握手指令报文字节2";
CM_ SG_ 2149220219 P2D_DLoadInfo_Data3 "发送的flash程序页下载握手指令报文字节3";
CM_ SG_ 2149220219 P2D_DLoadInfo_Data4 "发送的flash程序页下载握手指令报文字节4";
CM_ SG_ 2149220219 P2D_DLoadInfo_Data5 "发送的flash程序页下载握手指令报文字节5";
CM_ SG_ 2149220219 P2D_DLoadInfo_Data6 "发送的flash程序页下载握手指令报文字节6";
CM_ SG_ 2149220219 P2D_DLoadInfo_Data7 "发送的flash程序页下载握手指令报文字节7";
CM_ SG_ 2149220220 P2D_DLoadInfo_Data0 "发送的flash程序页下载握手指令报文字节0";
CM_ SG_ 2149220220 P2D_DLoadInfo_Data1 "发送的flash程序页下载握手指令报文字节1";
CM_ SG_ 2149220220 P2D_DLoadInfo_Data2 "发送的flash程序页下载握手指令报文字节2";
CM_ SG_ 2149220220 P2D_DLoadInfo_Data3 "发送的flash程序页下载握手指令报文字节3";
CM_ SG_ 2149220220 P2D_DLoadInfo_Data4 "发送的flash程序页下载握手指令报文字节4";
CM_ SG_ 2149220220 P2D_DLoadInfo_Data5 "发送的flash程序页下载握手指令报文字节5";
CM_ SG_ 2149220220 P2D_DLoadInfo_Data6 "发送的flash程序页下载握手指令报文字节6";
CM_ SG_ 2149220220 P2D_DLoadInfo_Data7 "发送的flash程序页下载握手指令报文字节7";
CM_ SG_ 2149220221 P2D_DLoadInfo_Data0 "发送的flash程序页下载握手指令报文字节0";
CM_ SG_ 2149220221 P2D_DLoadInfo_Data1 "发送的flash程序页下载握手指令报文字节1";
CM_ SG_ 2149220221 P2D_DLoadInfo_Data2 "发送的flash程序页下载握手指令报文字节2";
CM_ SG_ 2149220221 P2D_DLoadInfo_Data3 "发送的flash程序页下载握手指令报文字节3";
CM_ SG_ 2149220221 P2D_DLoadInfo_Data4 "发送的flash程序页下载握手指令报文字节4";
CM_ SG_ 2149220221 P2D_DLoadInfo_Data5 "发送的flash程序页下载握手指令报文字节5";
CM_ SG_ 2149220221 P2D_DLoadInfo_Data6 "发送的flash程序页下载握手指令报文字节6";
CM_ SG_ 2149220221 P2D_DLoadInfo_Data7 "发送的flash程序页下载握手指令报文字节7";
CM_ SG_ 2149220222 P2D_DLoadInfo_Data0 "发送的flash程序页下载握手指令报文字节0";
CM_ SG_ 2149220222 P2D_DLoadInfo_Data1 "发送的flash程序页下载握手指令报文字节1";
CM_ SG_ 2149220222 P2D_DLoadInfo_Data2 "发送的flash程序页下载握手指令报文字节2";
CM_ SG_ 2149220222 P2D_DLoadInfo_Data3 "发送的flash程序页下载握手指令报文字节3";
CM_ SG_ 2149220222 P2D_DLoadInfo_Data4 "发送的flash程序页下载握手指令报文字节4";
CM_ SG_ 2149220222 P2D_DLoadInfo_Data5 "发送的flash程序页下载握手指令报文字节5";
CM_ SG_ 2149220222 P2D_DLoadInfo_Data6 "发送的flash程序页下载握手指令报文字节6";
CM_ SG_ 2149220222 P2D_DLoadInfo_Data7 "发送的flash程序页下载握手指令报文字节7";
CM_ SG_ 2149220223 P2D_DLoadInfo_Data0 "发送的flash程序页下载握手指令报文字节0";
CM_ SG_ 2149220223 P2D_DLoadInfo_Data1 "发送的flash程序页下载握手指令报文字节1";
CM_ SG_ 2149220223 P2D_DLoadInfo_Data2 "发送的flash程序页下载握手指令报文字节2";
CM_ SG_ 2149220223 P2D_DLoadInfo_Data3 "发送的flash程序页下载握手指令报文字节3";
CM_ SG_ 2149220223 P2D_DLoadInfo_Data4 "发送的flash程序页下载握手指令报文字节4";
CM_ SG_ 2149220223 P2D_DLoadInfo_Data5 "发送的flash程序页下载握手指令报文字节5";
CM_ SG_ 2149220223 P2D_DLoadInfo_Data6 "发送的flash程序页下载握手指令报文字节6";
CM_ SG_ 2149220223 P2D_DLoadInfo_Data7 "发送的flash程序页下载握手指令报文字节7";
CM_ SG_ 2149285697 P2D_PrgData_Data0 "发送的flash数据报文字节0";
CM_ SG_ 2149285697 P2D_PrgData_Data1 "发送的flash数据报文字节1";
CM_ SG_ 2149285697 P2D_PrgData_Data2 "发送的flash数据报文字节2";
CM_ SG_ 2149285697 P2D_PrgData_Data3 "发送的flash数据报文字节3";
CM_ SG_ 2149285697 P2D_PrgData_Data4 "发送的flash数据报文字节4";
CM_ SG_ 2149285697 P2D_PrgData_Data5 "发送的flash数据报文字节5";
CM_ SG_ 2149285697 P2D_PrgData_Data6 "发送的flash数据报文字节6";
CM_ SG_ 2149285697 P2D_PrgData_Data7 "发送的flash数据报文字节7";
CM_ SG_ 2149285698 P2D_PrgData_Data0 "发送的flash数据报文字节0";
CM_ SG_ 2149285698 P2D_PrgData_Data1 "发送的flash数据报文字节1";
CM_ SG_ 2149285698 P2D_PrgData_Data2 "发送的flash数据报文字节2";
CM_ SG_ 2149285698 P2D_PrgData_Data3 "发送的flash数据报文字节3";
CM_ SG_ 2149285698 P2D_PrgData_Data4 "发送的flash数据报文字节4";
CM_ SG_ 2149285698 P2D_PrgData_Data5 "发送的flash数据报文字节5";
CM_ SG_ 2149285698 P2D_PrgData_Data6 "发送的flash数据报文字节6";
CM_ SG_ 2149285698 P2D_PrgData_Data7 "发送的flash数据报文字节7";
CM_ SG_ 2149285699 P2D_PrgData_Data0 "发送的flash数据报文字节0";
CM_ SG_ 2149285699 P2D_PrgData_Data1 "发送的flash数据报文字节1";
CM_ SG_ 2149285699 P2D_PrgData_Data2 "发送的flash数据报文字节2";
CM_ SG_ 2149285699 P2D_PrgData_Data3 "发送的flash数据报文字节3";
CM_ SG_ 2149285699 P2D_PrgData_Data4 "发送的flash数据报文字节4";
CM_ SG_ 2149285699 P2D_PrgData_Data5 "发送的flash数据报文字节5";
CM_ SG_ 2149285699 P2D_PrgData_Data6 "发送的flash数据报文字节6";
CM_ SG_ 2149285699 P2D_PrgData_Data7 "发送的flash数据报文字节7";
CM_ SG_ 2149285700 P2D_PrgData_Data0 "发送的flash数据报文字节0";
CM_ SG_ 2149285700 P2D_PrgData_Data1 "发送的flash数据报文字节1";
CM_ SG_ 2149285700 P2D_PrgData_Data2 "发送的flash数据报文字节2";
CM_ SG_ 2149285700 P2D_PrgData_Data3 "发送的flash数据报文字节3";
CM_ SG_ 2149285700 P2D_PrgData_Data4 "发送的flash数据报文字节4";
CM_ SG_ 2149285700 P2D_PrgData_Data5 "发送的flash数据报文字节5";
CM_ SG_ 2149285700 P2D_PrgData_Data6 "发送的flash数据报文字节6";
CM_ SG_ 2149285700 P2D_PrgData_Data7 "发送的flash数据报文字节7";
CM_ SG_ 2149285701 P2D_PrgData_Data0 "发送的flash数据报文字节0";
CM_ SG_ 2149285701 P2D_PrgData_Data1 "发送的flash数据报文字节1";
CM_ SG_ 2149285701 P2D_PrgData_Data2 "发送的flash数据报文字节2";
CM_ SG_ 2149285701 P2D_PrgData_Data3 "发送的flash数据报文字节3";
CM_ SG_ 2149285701 P2D_PrgData_Data4 "发送的flash数据报文字节4";
CM_ SG_ 2149285701 P2D_PrgData_Data5 "发送的flash数据报文字节5";
CM_ SG_ 2149285701 P2D_PrgData_Data6 "发送的flash数据报文字节6";
CM_ SG_ 2149285701 P2D_PrgData_Data7 "发送的flash数据报文字节7";
CM_ SG_ 2149285702 P2D_PrgData_Data0 "发送的flash数据报文字节0";
CM_ SG_ 2149285702 P2D_PrgData_Data1 "发送的flash数据报文字节1";
CM_ SG_ 2149285702 P2D_PrgData_Data2 "发送的flash数据报文字节2";
CM_ SG_ 2149285702 P2D_PrgData_Data3 "发送的flash数据报文字节3";
CM_ SG_ 2149285702 P2D_PrgData_Data4 "发送的flash数据报文字节4";
CM_ SG_ 2149285702 P2D_PrgData_Data5 "发送的flash数据报文字节5";
CM_ SG_ 2149285702 P2D_PrgData_Data6 "发送的flash数据报文字节6";
CM_ SG_ 2149285702 P2D_PrgData_Data7 "发送的flash数据报文字节7";
CM_ SG_ 2149285703 P2D_PrgData_Data0 "发送的flash数据报文字节0";
CM_ SG_ 2149285703 P2D_PrgData_Data1 "发送的flash数据报文字节1";
CM_ SG_ 2149285703 P2D_PrgData_Data2 "发送的flash数据报文字节2";
CM_ SG_ 2149285703 P2D_PrgData_Data3 "发送的flash数据报文字节3";
CM_ SG_ 2149285703 P2D_PrgData_Data4 "发送的flash数据报文字节4";
CM_ SG_ 2149285703 P2D_PrgData_Data5 "发送的flash数据报文字节5";
CM_ SG_ 2149285703 P2D_PrgData_Data6 "发送的flash数据报文字节6";
CM_ SG_ 2149285703 P2D_PrgData_Data7 "发送的flash数据报文字节7";
CM_ SG_ 2149285704 P2D_PrgData_Data0 "发送的flash数据报文字节0";
CM_ SG_ 2149285704 P2D_PrgData_Data1 "发送的flash数据报文字节1";
CM_ SG_ 2149285704 P2D_PrgData_Data2 "发送的flash数据报文字节2";
CM_ SG_ 2149285704 P2D_PrgData_Data3 "发送的flash数据报文字节3";
CM_ SG_ 2149285704 P2D_PrgData_Data4 "发送的flash数据报文字节4";
CM_ SG_ 2149285704 P2D_PrgData_Data5 "发送的flash数据报文字节5";
CM_ SG_ 2149285704 P2D_PrgData_Data6 "发送的flash数据报文字节6";
CM_ SG_ 2149285704 P2D_PrgData_Data7 "发送的flash数据报文字节7";
CM_ SG_ 2149285705 P2D_PrgData_Data0 "发送的flash数据报文字节0";
CM_ SG_ 2149285705 P2D_PrgData_Data1 "发送的flash数据报文字节1";
CM_ SG_ 2149285705 P2D_PrgData_Data2 "发送的flash数据报文字节2";
CM_ SG_ 2149285705 P2D_PrgData_Data3 "发送的flash数据报文字节3";
CM_ SG_ 2149285705 P2D_PrgData_Data4 "发送的flash数据报文字节4";
CM_ SG_ 2149285705 P2D_PrgData_Data5 "发送的flash数据报文字节5";
CM_ SG_ 2149285705 P2D_PrgData_Data6 "发送的flash数据报文字节6";
CM_ SG_ 2149285705 P2D_PrgData_Data7 "发送的flash数据报文字节7";
CM_ SG_ 2149285706 P2D_PrgData_Data0 "发送的flash数据报文字节0";
CM_ SG_ 2149285706 P2D_PrgData_Data1 "发送的flash数据报文字节1";
CM_ SG_ 2149285706 P2D_PrgData_Data2 "发送的flash数据报文字节2";
CM_ SG_ 2149285706 P2D_PrgData_Data3 "发送的flash数据报文字节3";
CM_ SG_ 2149285706 P2D_PrgData_Data4 "发送的flash数据报文字节4";
CM_ SG_ 2149285706 P2D_PrgData_Data5 "发送的flash数据报文字节5";
CM_ SG_ 2149285706 P2D_PrgData_Data6 "发送的flash数据报文字节6";
CM_ SG_ 2149285706 P2D_PrgData_Data7 "发送的flash数据报文字节7";
CM_ SG_ 2149285707 P2D_PrgData_Data0 "发送的flash数据报文字节0";
CM_ SG_ 2149285707 P2D_PrgData_Data1 "发送的flash数据报文字节1";
CM_ SG_ 2149285707 P2D_PrgData_Data2 "发送的flash数据报文字节2";
CM_ SG_ 2149285707 P2D_PrgData_Data3 "发送的flash数据报文字节3";
CM_ SG_ 2149285707 P2D_PrgData_Data4 "发送的flash数据报文字节4";
CM_ SG_ 2149285707 P2D_PrgData_Data5 "发送的flash数据报文字节5";
CM_ SG_ 2149285707 P2D_PrgData_Data6 "发送的flash数据报文字节6";
CM_ SG_ 2149285707 P2D_PrgData_Data7 "发送的flash数据报文字节7";
CM_ SG_ 2149285708 P2D_PrgData_Data0 "发送的flash数据报文字节0";
CM_ SG_ 2149285708 P2D_PrgData_Data1 "发送的flash数据报文字节1";
CM_ SG_ 2149285708 P2D_PrgData_Data2 "发送的flash数据报文字节2";
CM_ SG_ 2149285708 P2D_PrgData_Data3 "发送的flash数据报文字节3";
CM_ SG_ 2149285708 P2D_PrgData_Data4 "发送的flash数据报文字节4";
CM_ SG_ 2149285708 P2D_PrgData_Data5 "发送的flash数据报文字节5";
CM_ SG_ 2149285708 P2D_PrgData_Data6 "发送的flash数据报文字节6";
CM_ SG_ 2149285708 P2D_PrgData_Data7 "发送的flash数据报文字节7";
CM_ SG_ 2149285709 P2D_PrgData_Data0 "发送的flash数据报文字节0";
CM_ SG_ 2149285709 P2D_PrgData_Data1 "发送的flash数据报文字节1";
CM_ SG_ 2149285709 P2D_PrgData_Data2 "发送的flash数据报文字节2";
CM_ SG_ 2149285709 P2D_PrgData_Data3 "发送的flash数据报文字节3";
CM_ SG_ 2149285709 P2D_PrgData_Data4 "发送的flash数据报文字节4";
CM_ SG_ 2149285709 P2D_PrgData_Data5 "发送的flash数据报文字节5";
CM_ SG_ 2149285709 P2D_PrgData_Data6 "发送的flash数据报文字节6";
CM_ SG_ 2149285709 P2D_PrgData_Data7 "发送的flash数据报文字节7";
CM_ SG_ 2149285710 P2D_PrgData_Data0 "发送的flash数据报文字节0";
CM_ SG_ 2149285710 P2D_PrgData_Data1 "发送的flash数据报文字节1";
CM_ SG_ 2149285710 P2D_PrgData_Data2 "发送的flash数据报文字节2";
CM_ SG_ 2149285710 P2D_PrgData_Data3 "发送的flash数据报文字节3";
CM_ SG_ 2149285710 P2D_PrgData_Data4 "发送的flash数据报文字节4";
CM_ SG_ 2149285710 P2D_PrgData_Data5 "发送的flash数据报文字节5";
CM_ SG_ 2149285710 P2D_PrgData_Data6 "发送的flash数据报文字节6";
CM_ SG_ 2149285710 P2D_PrgData_Data7 "发送的flash数据报文字节7";
CM_ SG_ 2149285711 P2D_PrgData_Data0 "发送的flash数据报文字节0";
CM_ SG_ 2149285711 P2D_PrgData_Data1 "发送的flash数据报文字节1";
CM_ SG_ 2149285711 P2D_PrgData_Data2 "发送的flash数据报文字节2";
CM_ SG_ 2149285711 P2D_PrgData_Data3 "发送的flash数据报文字节3";
CM_ SG_ 2149285711 P2D_PrgData_Data4 "发送的flash数据报文字节4";
CM_ SG_ 2149285711 P2D_PrgData_Data5 "发送的flash数据报文字节5";
CM_ SG_ 2149285711 P2D_PrgData_Data6 "发送的flash数据报文字节6";
CM_ SG_ 2149285711 P2D_PrgData_Data7 "发送的flash数据报文字节7";
CM_ SG_ 2149285712 P2D_PrgData_Data0 "发送的flash数据报文字节0";
CM_ SG_ 2149285712 P2D_PrgData_Data1 "发送的flash数据报文字节1";
CM_ SG_ 2149285712 P2D_PrgData_Data2 "发送的flash数据报文字节2";
CM_ SG_ 2149285712 P2D_PrgData_Data3 "发送的flash数据报文字节3";
CM_ SG_ 2149285712 P2D_PrgData_Data4 "发送的flash数据报文字节4";
CM_ SG_ 2149285712 P2D_PrgData_Data5 "发送的flash数据报文字节5";
CM_ SG_ 2149285712 P2D_PrgData_Data6 "发送的flash数据报文字节6";
CM_ SG_ 2149285712 P2D_PrgData_Data7 "发送的flash数据报文字节7";
CM_ SG_ 2149285713 P2D_PrgData_Data0 "发送的flash数据报文字节0";
CM_ SG_ 2149285713 P2D_PrgData_Data1 "发送的flash数据报文字节1";
CM_ SG_ 2149285713 P2D_PrgData_Data2 "发送的flash数据报文字节2";
CM_ SG_ 2149285713 P2D_PrgData_Data3 "发送的flash数据报文字节3";
CM_ SG_ 2149285713 P2D_PrgData_Data4 "发送的flash数据报文字节4";
CM_ SG_ 2149285713 P2D_PrgData_Data5 "发送的flash数据报文字节5";
CM_ SG_ 2149285713 P2D_PrgData_Data6 "发送的flash数据报文字节6";
CM_ SG_ 2149285713 P2D_PrgData_Data7 "发送的flash数据报文字节7";
CM_ SG_ 2149285714 P2D_PrgData_Data0 "发送的flash数据报文字节0";
CM_ SG_ 2149285714 P2D_PrgData_Data1 "发送的flash数据报文字节1";
CM_ SG_ 2149285714 P2D_PrgData_Data2 "发送的flash数据报文字节2";
CM_ SG_ 2149285714 P2D_PrgData_Data3 "发送的flash数据报文字节3";
CM_ SG_ 2149285714 P2D_PrgData_Data4 "发送的flash数据报文字节4";
CM_ SG_ 2149285714 P2D_PrgData_Data5 "发送的flash数据报文字节5";
CM_ SG_ 2149285714 P2D_PrgData_Data6 "发送的flash数据报文字节6";
CM_ SG_ 2149285714 P2D_PrgData_Data7 "发送的flash数据报文字节7";
CM_ SG_ 2149285715 P2D_PrgData_Data0 "发送的flash数据报文字节0";
CM_ SG_ 2149285715 P2D_PrgData_Data1 "发送的flash数据报文字节1";
CM_ SG_ 2149285715 P2D_PrgData_Data2 "发送的flash数据报文字节2";
CM_ SG_ 2149285715 P2D_PrgData_Data3 "发送的flash数据报文字节3";
CM_ SG_ 2149285715 P2D_PrgData_Data4 "发送的flash数据报文字节4";
CM_ SG_ 2149285715 P2D_PrgData_Data5 "发送的flash数据报文字节5";
CM_ SG_ 2149285715 P2D_PrgData_Data6 "发送的flash数据报文字节6";
CM_ SG_ 2149285715 P2D_PrgData_Data7 "发送的flash数据报文字节7";
CM_ SG_ 2149285716 P2D_PrgData_Data0 "发送的flash数据报文字节0";
CM_ SG_ 2149285716 P2D_PrgData_Data1 "发送的flash数据报文字节1";
CM_ SG_ 2149285716 P2D_PrgData_Data2 "发送的flash数据报文字节2";
CM_ SG_ 2149285716 P2D_PrgData_Data3 "发送的flash数据报文字节3";
CM_ SG_ 2149285716 P2D_PrgData_Data4 "发送的flash数据报文字节4";
CM_ SG_ 2149285716 P2D_PrgData_Data5 "发送的flash数据报文字节5";
CM_ SG_ 2149285716 P2D_PrgData_Data6 "发送的flash数据报文字节6";
CM_ SG_ 2149285716 P2D_PrgData_Data7 "发送的flash数据报文字节7";
CM_ SG_ 2149285717 P2D_PrgData_Data0 "发送的flash数据报文字节0";
CM_ SG_ 2149285717 P2D_PrgData_Data1 "发送的flash数据报文字节1";
CM_ SG_ 2149285717 P2D_PrgData_Data2 "发送的flash数据报文字节2";
CM_ SG_ 2149285717 P2D_PrgData_Data3 "发送的flash数据报文字节3";
CM_ SG_ 2149285717 P2D_PrgData_Data4 "发送的flash数据报文字节4";
CM_ SG_ 2149285717 P2D_PrgData_Data5 "发送的flash数据报文字节5";
CM_ SG_ 2149285717 P2D_PrgData_Data6 "发送的flash数据报文字节6";
CM_ SG_ 2149285717 P2D_PrgData_Data7 "发送的flash数据报文字节7";
CM_ SG_ 2149285718 P2D_PrgData_Data0 "发送的flash数据报文字节0";
CM_ SG_ 2149285718 P2D_PrgData_Data1 "发送的flash数据报文字节1";
CM_ SG_ 2149285718 P2D_PrgData_Data2 "发送的flash数据报文字节2";
CM_ SG_ 2149285718 P2D_PrgData_Data3 "发送的flash数据报文字节3";
CM_ SG_ 2149285718 P2D_PrgData_Data4 "发送的flash数据报文字节4";
CM_ SG_ 2149285718 P2D_PrgData_Data5 "发送的flash数据报文字节5";
CM_ SG_ 2149285718 P2D_PrgData_Data6 "发送的flash数据报文字节6";
CM_ SG_ 2149285718 P2D_PrgData_Data7 "发送的flash数据报文字节7";
CM_ SG_ 2149285719 P2D_PrgData_Data0 "发送的flash数据报文字节0";
CM_ SG_ 2149285719 P2D_PrgData_Data1 "发送的flash数据报文字节1";
CM_ SG_ 2149285719 P2D_PrgData_Data2 "发送的flash数据报文字节2";
CM_ SG_ 2149285719 P2D_PrgData_Data3 "发送的flash数据报文字节3";
CM_ SG_ 2149285719 P2D_PrgData_Data4 "发送的flash数据报文字节4";
CM_ SG_ 2149285719 P2D_PrgData_Data5 "发送的flash数据报文字节5";
CM_ SG_ 2149285719 P2D_PrgData_Data6 "发送的flash数据报文字节6";
CM_ SG_ 2149285719 P2D_PrgData_Data7 "发送的flash数据报文字节7";
CM_ SG_ 2149285720 P2D_PrgData_Data0 "发送的flash数据报文字节0";
CM_ SG_ 2149285720 P2D_PrgData_Data1 "发送的flash数据报文字节1";
CM_ SG_ 2149285720 P2D_PrgData_Data2 "发送的flash数据报文字节2";
CM_ SG_ 2149285720 P2D_PrgData_Data3 "发送的flash数据报文字节3";
CM_ SG_ 2149285720 P2D_PrgData_Data4 "发送的flash数据报文字节4";
CM_ SG_ 2149285720 P2D_PrgData_Data5 "发送的flash数据报文字节5";
CM_ SG_ 2149285720 P2D_PrgData_Data6 "发送的flash数据报文字节6";
CM_ SG_ 2149285720 P2D_PrgData_Data7 "发送的flash数据报文字节7";
VERSION ""

NS_ :

BS_:

BU_: MBMU PC SBMU IMM ETH DCDC LEMS

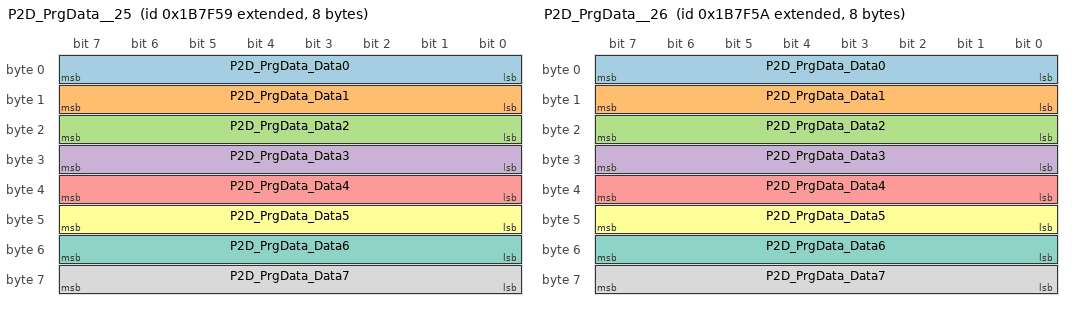
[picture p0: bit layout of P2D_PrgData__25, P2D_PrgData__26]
BO_ 2149285721 P2D_PrgData__25: 8 PC
 SG_ P2D_PrgData_Data0 : 0|8@1+ (1,0) [0|255] ""  DCDC
 SG_ P2D_PrgData_Data1 : 8|8@1+ (1,0) [0|255] ""  DCDC
 SG_ P2D_PrgData_Data2 : 16|8@1+ (1,0) [0|255] ""  DCDC
 SG_ P2D_PrgData_Data3 : 24|8@1+ (1,0) [0|255] ""  DCDC
 SG_ P2D_PrgData_Data4 : 32|8@1+ (1,0) [0|255] ""  DCDC
 SG_ P2D_PrgData_Data5 : 40|8@1+ (1,0) [0|255] ""  DCDC
 SG_ P2D_PrgData_Data6 : 48|8@1+ (1,0) [0|255] ""  DCDC
 SG_ P2D_PrgData_Data7 : 56|8@1+ (1,0) [0|255] ""  DCDC

BO_ 2149285722 P2D_PrgData__26: 8 PC
 SG_ P2D_PrgData_Data0 : 0|8@1+ (1,0) [0|255] ""  DCDC
 SG_ P2D_PrgData_Data1 : 8|8@1+ (1,0) [0|255] ""  DCDC
 SG_ P2D_PrgData_Data2 : 16|8@1+ (1,0) [0|255] ""  DCDC
 SG_ P2D_PrgData_Data3 : 24|8@1+ (1,0) [0|255] ""  DCDC
 SG_ P2D_PrgData_Data4 : 32|8@1+ (1,0) [0|255] ""  DCDC
 SG_ P2D_PrgData_Data5 : 40|8@1+ (1,0) [0|255] ""  DCDC
 SG_ P2D_PrgData_Data6 : 48|8@1+ (1,0) [0|255] ""  DCDC
 SG_ P2D_PrgData_Data7 : 56|8@1+ (1,0) [0|255] ""  DCDC

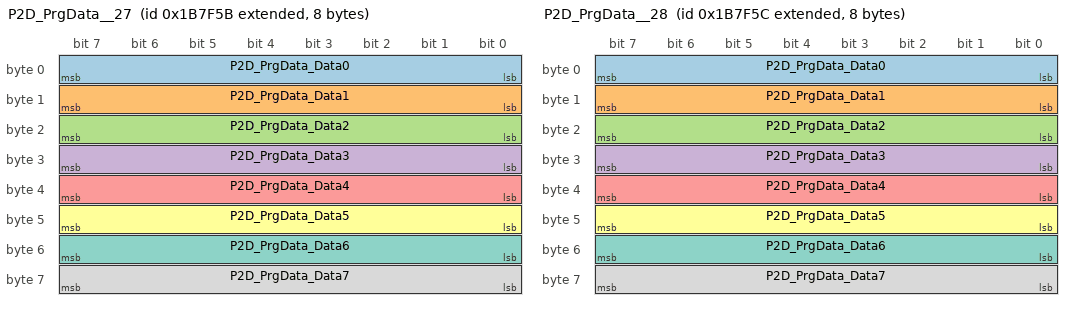
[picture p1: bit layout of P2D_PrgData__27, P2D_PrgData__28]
BO_ 2149285723 P2D_PrgData__27: 8 PC
 SG_ P2D_PrgData_Data0 : 0|8@1+ (1,0) [0|255] ""  DCDC
 SG_ P2D_PrgData_Data1 : 8|8@1+ (1,0) [0|255] ""  DCDC
 SG_ P2D_PrgData_Data2 : 16|8@1+ (1,0) [0|255] ""  DCDC
 SG_ P2D_PrgData_Data3 : 24|8@1+ (1,0) [0|255] ""  DCDC
 SG_ P2D_PrgData_Data4 : 32|8@1+ (1,0) [0|255] ""  DCDC
 SG_ P2D_PrgData_Data5 : 40|8@1+ (1,0) [0|255] ""  DCDC
 SG_ P2D_PrgData_Data6 : 48|8@1+ (1,0) [0|255] ""  DCDC
 SG_ P2D_PrgData_Data7 : 56|8@1+ (1,0) [0|255] ""  DCDC

BO_ 2149285724 P2D_PrgData__28: 8 PC
 SG_ P2D_PrgData_Data0 : 0|8@1+ (1,0) [0|255] ""  DCDC
 SG_ P2D_PrgData_Data1 : 8|8@1+ (1,0) [0|255] ""  DCDC
 SG_ P2D_PrgData_Data2 : 16|8@1+ (1,0) [0|255] ""  DCDC
 SG_ P2D_PrgData_Data3 : 24|8@1+ (1,0) [0|255] ""  DCDC
 SG_ P2D_PrgData_Data4 : 32|8@1+ (1,0) [0|255] ""  DCDC
 SG_ P2D_PrgData_Data5 : 40|8@1+ (1,0) [0|255] ""  DCDC
 SG_ P2D_PrgData_Data6 : 48|8@1+ (1,0) [0|255] ""  DCDC
 SG_ P2D_PrgData_Data7 : 56|8@1+ (1,0) [0|255] ""  DCDC

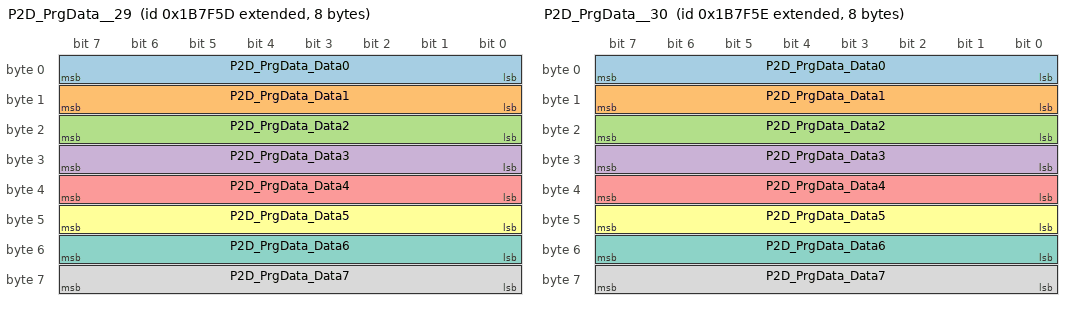
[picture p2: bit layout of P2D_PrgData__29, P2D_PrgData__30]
BO_ 2149285725 P2D_PrgData__29: 8 PC
 SG_ P2D_PrgData_Data0 : 0|8@1+ (1,0) [0|255] ""  DCDC
 SG_ P2D_PrgData_Data1 : 8|8@1+ (1,0) [0|255] ""  DCDC
 SG_ P2D_PrgData_Data2 : 16|8@1+ (1,0) [0|255] ""  DCDC
 SG_ P2D_PrgData_Data3 : 24|8@1+ (1,0) [0|255] ""  DCDC
 SG_ P2D_PrgData_Data4 : 32|8@1+ (1,0) [0|255] ""  DCDC
 SG_ P2D_PrgData_Data5 : 40|8@1+ (1,0) [0|255] ""  DCDC
 SG_ P2D_PrgData_Data6 : 48|8@1+ (1,0) [0|255] ""  DCDC
 SG_ P2D_PrgData_Data7 : 56|8@1+ (1,0) [0|255] ""  DCDC

BO_ 2149285726 P2D_PrgData__30: 8 PC
 SG_ P2D_PrgData_Data0 : 0|8@1+ (1,0) [0|255] ""  DCDC
 SG_ P2D_PrgData_Data1 : 8|8@1+ (1,0) [0|255] ""  DCDC
 SG_ P2D_PrgData_Data2 : 16|8@1+ (1,0) [0|255] ""  DCDC
 SG_ P2D_PrgData_Data3 : 24|8@1+ (1,0) [0|255] ""  DCDC
 SG_ P2D_PrgData_Data4 : 32|8@1+ (1,0) [0|255] ""  DCDC
 SG_ P2D_PrgData_Data5 : 40|8@1+ (1,0) [0|255] ""  DCDC
 SG_ P2D_PrgData_Data6 : 48|8@1+ (1,0) [0|255] ""  DCDC
 SG_ P2D_PrgData_Data7 : 56|8@1+ (1,0) [0|255] ""  DCDC

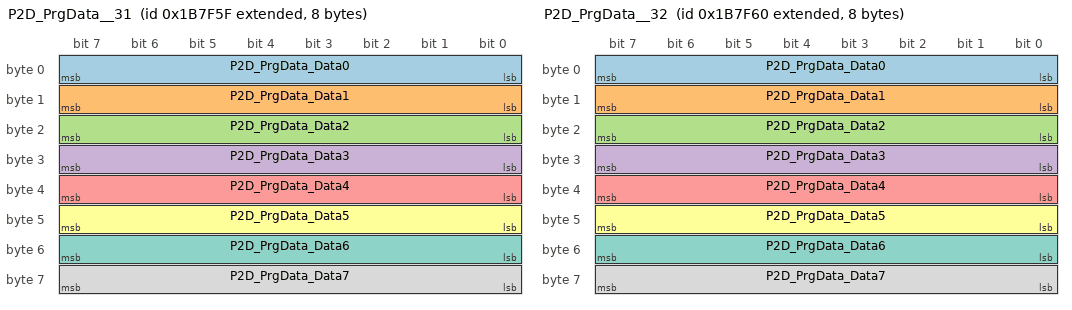
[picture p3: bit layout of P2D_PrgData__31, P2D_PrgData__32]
BO_ 2149285727 P2D_PrgData__31: 8 PC
 SG_ P2D_PrgData_Data0 : 0|8@1+ (1,0) [0|255] ""  DCDC
 SG_ P2D_PrgData_Data1 : 8|8@1+ (1,0) [0|255] ""  DCDC
 SG_ P2D_PrgData_Data2 : 16|8@1+ (1,0) [0|255] ""  DCDC
 SG_ P2D_PrgData_Data3 : 24|8@1+ (1,0) [0|255] ""  DCDC
 SG_ P2D_PrgData_Data4 : 32|8@1+ (1,0) [0|255] ""  DCDC
 SG_ P2D_PrgData_Data5 : 40|8@1+ (1,0) [0|255] ""  DCDC
 SG_ P2D_PrgData_Data6 : 48|8@1+ (1,0) [0|255] ""  DCDC
 SG_ P2D_PrgData_Data7 : 56|8@1+ (1,0) [0|255] ""  DCDC

BO_ 2149285728 P2D_PrgData__32: 8 PC
 SG_ P2D_PrgData_Data0 : 0|8@1+ (1,0) [0|255] ""  DCDC
 SG_ P2D_PrgData_Data1 : 8|8@1+ (1,0) [0|255] ""  DCDC
 SG_ P2D_PrgData_Data2 : 16|8@1+ (1,0) [0|255] ""  DCDC
 SG_ P2D_PrgData_Data3 : 24|8@1+ (1,0) [0|255] ""  DCDC
 SG_ P2D_PrgData_Data4 : 32|8@1+ (1,0) [0|255] ""  DCDC
 SG_ P2D_PrgData_Data5 : 40|8@1+ (1,0) [0|255] ""  DCDC
 SG_ P2D_PrgData_Data6 : 48|8@1+ (1,0) [0|255] ""  DCDC
 SG_ P2D_PrgData_Data7 : 56|8@1+ (1,0) [0|255] ""  DCDC

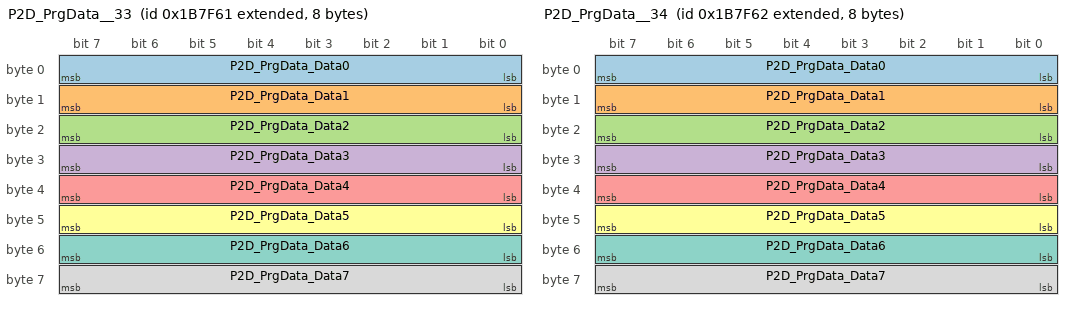
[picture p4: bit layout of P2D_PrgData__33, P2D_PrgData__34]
BO_ 2149285729 P2D_PrgData__33: 8 PC
 SG_ P2D_PrgData_Data0 : 0|8@1+ (1,0) [0|255] ""  DCDC
 SG_ P2D_PrgData_Data1 : 8|8@1+ (1,0) [0|255] ""  DCDC
 SG_ P2D_PrgData_Data2 : 16|8@1+ (1,0) [0|255] ""  DCDC
 SG_ P2D_PrgData_Data3 : 24|8@1+ (1,0) [0|255] ""  DCDC
 SG_ P2D_PrgData_Data4 : 32|8@1+ (1,0) [0|255] ""  DCDC
 SG_ P2D_PrgData_Data5 : 40|8@1+ (1,0) [0|255] ""  DCDC
 SG_ P2D_PrgData_Data6 : 48|8@1+ (1,0) [0|255] ""  DCDC
 SG_ P2D_PrgData_Data7 : 56|8@1+ (1,0) [0|255] ""  DCDC

BO_ 2149285730 P2D_PrgData__34: 8 PC
 SG_ P2D_PrgData_Data0 : 0|8@1+ (1,0) [0|255] ""  DCDC
 SG_ P2D_PrgData_Data1 : 8|8@1+ (1,0) [0|255] ""  DCDC
 SG_ P2D_PrgData_Data2 : 16|8@1+ (1,0) [0|255] ""  DCDC
 SG_ P2D_PrgData_Data3 : 24|8@1+ (1,0) [0|255] ""  DCDC
 SG_ P2D_PrgData_Data4 : 32|8@1+ (1,0) [0|255] ""  DCDC
 SG_ P2D_PrgData_Data5 : 40|8@1+ (1,0) [0|255] ""  DCDC
 SG_ P2D_PrgData_Data6 : 48|8@1+ (1,0) [0|255] ""  DCDC
 SG_ P2D_PrgData_Data7 : 56|8@1+ (1,0) [0|255] ""  DCDC

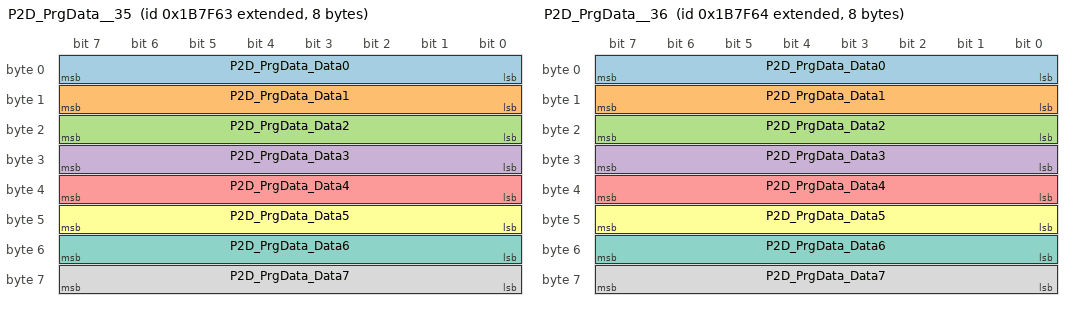
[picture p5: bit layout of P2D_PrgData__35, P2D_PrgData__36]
BO_ 2149285731 P2D_PrgData__35: 8 PC
 SG_ P2D_PrgData_Data0 : 0|8@1+ (1,0) [0|255] ""  DCDC
 SG_ P2D_PrgData_Data1 : 8|8@1+ (1,0) [0|255] ""  DCDC
 SG_ P2D_PrgData_Data2 : 16|8@1+ (1,0) [0|255] ""  DCDC
 SG_ P2D_PrgData_Data3 : 24|8@1+ (1,0) [0|255] ""  DCDC
 SG_ P2D_PrgData_Data4 : 32|8@1+ (1,0) [0|255] ""  DCDC
 SG_ P2D_PrgData_Data5 : 40|8@1+ (1,0) [0|255] ""  DCDC
 SG_ P2D_PrgData_Data6 : 48|8@1+ (1,0) [0|255] ""  DCDC
 SG_ P2D_PrgData_Data7 : 56|8@1+ (1,0) [0|255] ""  DCDC

BO_ 2149285732 P2D_PrgData__36: 8 PC
 SG_ P2D_PrgData_Data0 : 0|8@1+ (1,0) [0|255] ""  DCDC
 SG_ P2D_PrgData_Data1 : 8|8@1+ (1,0) [0|255] ""  DCDC
 SG_ P2D_PrgData_Data2 : 16|8@1+ (1,0) [0|255] ""  DCDC
 SG_ P2D_PrgData_Data3 : 24|8@1+ (1,0) [0|255] ""  DCDC
 SG_ P2D_PrgData_Data4 : 32|8@1+ (1,0) [0|255] ""  DCDC
 SG_ P2D_PrgData_Data5 : 40|8@1+ (1,0) [0|255] ""  DCDC
 SG_ P2D_PrgData_Data6 : 48|8@1+ (1,0) [0|255] ""  DCDC
 SG_ P2D_PrgData_Data7 : 56|8@1+ (1,0) [0|255] ""  DCDC

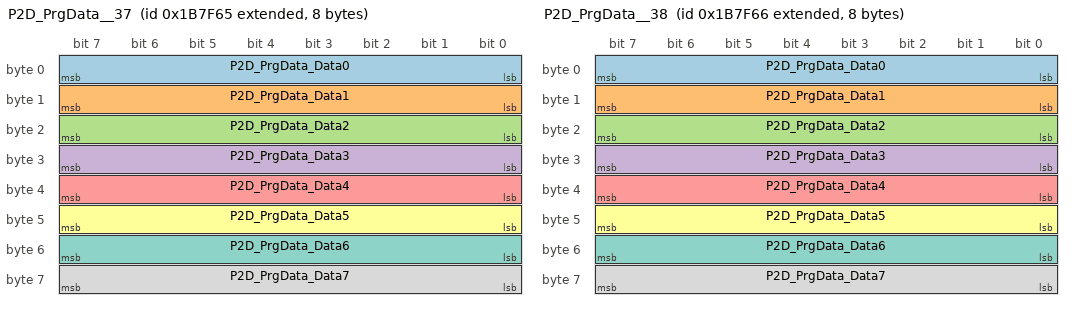
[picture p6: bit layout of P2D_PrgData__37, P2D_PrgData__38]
BO_ 2149285733 P2D_PrgData__37: 8 PC
 SG_ P2D_PrgData_Data0 : 0|8@1+ (1,0) [0|255] ""  DCDC
 SG_ P2D_PrgData_Data1 : 8|8@1+ (1,0) [0|255] ""  DCDC
 SG_ P2D_PrgData_Data2 : 16|8@1+ (1,0) [0|255] ""  DCDC
 SG_ P2D_PrgData_Data3 : 24|8@1+ (1,0) [0|255] ""  DCDC
 SG_ P2D_PrgData_Data4 : 32|8@1+ (1,0) [0|255] ""  DCDC
 SG_ P2D_PrgData_Data5 : 40|8@1+ (1,0) [0|255] ""  DCDC
 SG_ P2D_PrgData_Data6 : 48|8@1+ (1,0) [0|255] ""  DCDC
 SG_ P2D_PrgData_Data7 : 56|8@1+ (1,0) [0|255] ""  DCDC

BO_ 2149285734 P2D_PrgData__38: 8 PC
 SG_ P2D_PrgData_Data0 : 0|8@1+ (1,0) [0|255] ""  DCDC
 SG_ P2D_PrgData_Data1 : 8|8@1+ (1,0) [0|255] ""  DCDC
 SG_ P2D_PrgData_Data2 : 16|8@1+ (1,0) [0|255] ""  DCDC
 SG_ P2D_PrgData_Data3 : 24|8@1+ (1,0) [0|255] ""  DCDC
 SG_ P2D_PrgData_Data4 : 32|8@1+ (1,0) [0|255] ""  DCDC
 SG_ P2D_PrgData_Data5 : 40|8@1+ (1,0) [0|255] ""  DCDC
 SG_ P2D_PrgData_Data6 : 48|8@1+ (1,0) [0|255] ""  DCDC
 SG_ P2D_PrgData_Data7 : 56|8@1+ (1,0) [0|255] ""  DCDC

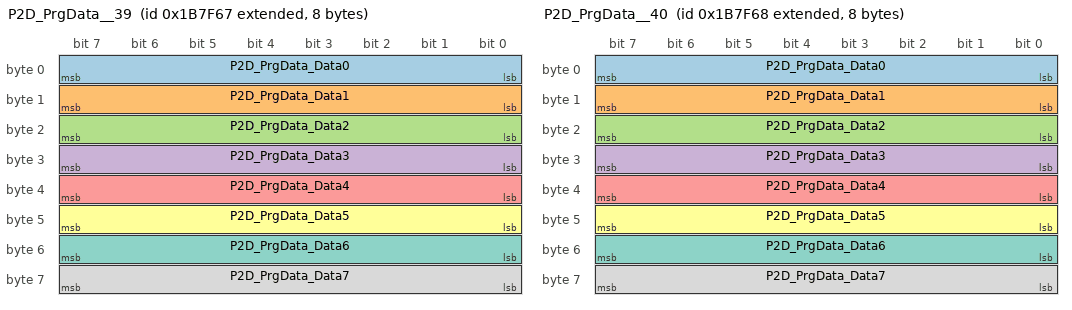
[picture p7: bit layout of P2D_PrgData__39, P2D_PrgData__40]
BO_ 2149285735 P2D_PrgData__39: 8 PC
 SG_ P2D_PrgData_Data0 : 0|8@1+ (1,0) [0|255] ""  DCDC
 SG_ P2D_PrgData_Data1 : 8|8@1+ (1,0) [0|255] ""  DCDC
 SG_ P2D_PrgData_Data2 : 16|8@1+ (1,0) [0|255] ""  DCDC
 SG_ P2D_PrgData_Data3 : 24|8@1+ (1,0) [0|255] ""  DCDC
 SG_ P2D_PrgData_Data4 : 32|8@1+ (1,0) [0|255] ""  DCDC
 SG_ P2D_PrgData_Data5 : 40|8@1+ (1,0) [0|255] ""  DCDC
 SG_ P2D_PrgData_Data6 : 48|8@1+ (1,0) [0|255] ""  DCDC
 SG_ P2D_PrgData_Data7 : 56|8@1+ (1,0) [0|255] ""  DCDC

BO_ 2149285736 P2D_PrgData__40: 8 PC
 SG_ P2D_PrgData_Data0 : 0|8@1+ (1,0) [0|255] ""  DCDC
 SG_ P2D_PrgData_Data1 : 8|8@1+ (1,0) [0|255] ""  DCDC
 SG_ P2D_PrgData_Data2 : 16|8@1+ (1,0) [0|255] ""  DCDC
 SG_ P2D_PrgData_Data3 : 24|8@1+ (1,0) [0|255] ""  DCDC
 SG_ P2D_PrgData_Data4 : 32|8@1+ (1,0) [0|255] ""  DCDC
 SG_ P2D_PrgData_Data5 : 40|8@1+ (1,0) [0|255] ""  DCDC
 SG_ P2D_PrgData_Data6 : 48|8@1+ (1,0) [0|255] ""  DCDC
 SG_ P2D_PrgData_Data7 : 56|8@1+ (1,0) [0|255] ""  DCDC

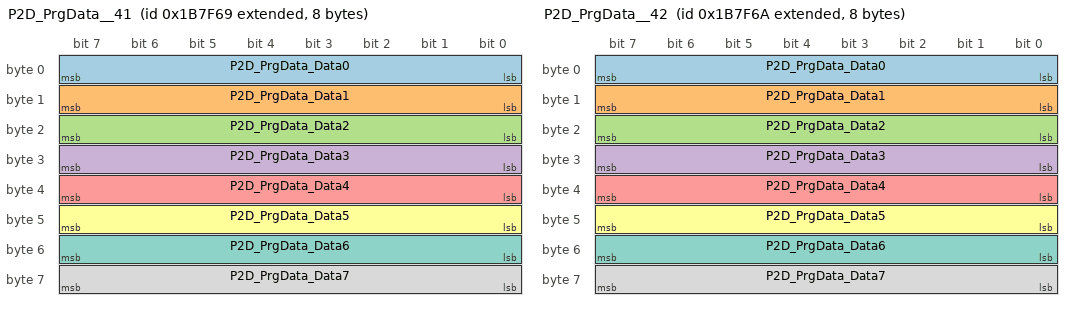
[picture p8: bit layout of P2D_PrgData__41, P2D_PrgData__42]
BO_ 2149285737 P2D_PrgData__41: 8 PC
 SG_ P2D_PrgData_Data0 : 0|8@1+ (1,0) [0|255] ""  DCDC
 SG_ P2D_PrgData_Data1 : 8|8@1+ (1,0) [0|255] ""  DCDC
 SG_ P2D_PrgData_Data2 : 16|8@1+ (1,0) [0|255] ""  DCDC
 SG_ P2D_PrgData_Data3 : 24|8@1+ (1,0) [0|255] ""  DCDC
 SG_ P2D_PrgData_Data4 : 32|8@1+ (1,0) [0|255] ""  DCDC
 SG_ P2D_PrgData_Data5 : 40|8@1+ (1,0) [0|255] ""  DCDC
 SG_ P2D_PrgData_Data6 : 48|8@1+ (1,0) [0|255] ""  DCDC
 SG_ P2D_PrgData_Data7 : 56|8@1+ (1,0) [0|255] ""  DCDC

BO_ 2149285738 P2D_PrgData__42: 8 PC
 SG_ P2D_PrgData_Data0 : 0|8@1+ (1,0) [0|255] ""  DCDC
 SG_ P2D_PrgData_Data1 : 8|8@1+ (1,0) [0|255] ""  DCDC
 SG_ P2D_PrgData_Data2 : 16|8@1+ (1,0) [0|255] ""  DCDC
 SG_ P2D_PrgData_Data3 : 24|8@1+ (1,0) [0|255] ""  DCDC
 SG_ P2D_PrgData_Data4 : 32|8@1+ (1,0) [0|255] ""  DCDC
 SG_ P2D_PrgData_Data5 : 40|8@1+ (1,0) [0|255] ""  DCDC
 SG_ P2D_PrgData_Data6 : 48|8@1+ (1,0) [0|255] ""  DCDC
 SG_ P2D_PrgData_Data7 : 56|8@1+ (1,0) [0|255] ""  DCDC

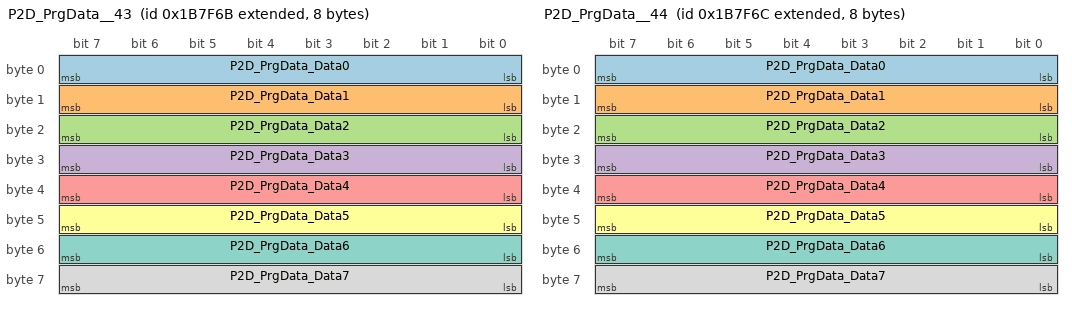
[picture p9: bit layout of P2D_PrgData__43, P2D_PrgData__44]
BO_ 2149285739 P2D_PrgData__43: 8 PC
 SG_ P2D_PrgData_Data0 : 0|8@1+ (1,0) [0|255] ""  DCDC
 SG_ P2D_PrgData_Data1 : 8|8@1+ (1,0) [0|255] ""  DCDC
 SG_ P2D_PrgData_Data2 : 16|8@1+ (1,0) [0|255] ""  DCDC
 SG_ P2D_PrgData_Data3 : 24|8@1+ (1,0) [0|255] ""  DCDC
 SG_ P2D_PrgData_Data4 : 32|8@1+ (1,0) [0|255] ""  DCDC
 SG_ P2D_PrgData_Data5 : 40|8@1+ (1,0) [0|255] ""  DCDC
 SG_ P2D_PrgData_Data6 : 48|8@1+ (1,0) [0|255] ""  DCDC
 SG_ P2D_PrgData_Data7 : 56|8@1+ (1,0) [0|255] ""  DCDC

BO_ 2149285740 P2D_PrgData__44: 8 PC
 SG_ P2D_PrgData_Data0 : 0|8@1+ (1,0) [0|255] ""  DCDC
 SG_ P2D_PrgData_Data1 : 8|8@1+ (1,0) [0|255] ""  DCDC
 SG_ P2D_PrgData_Data2 : 16|8@1+ (1,0) [0|255] ""  DCDC
 SG_ P2D_PrgData_Data3 : 24|8@1+ (1,0) [0|255] ""  DCDC
 SG_ P2D_PrgData_Data4 : 32|8@1+ (1,0) [0|255] ""  DCDC
 SG_ P2D_PrgData_Data5 : 40|8@1+ (1,0) [0|255] ""  DCDC
 SG_ P2D_PrgData_Data6 : 48|8@1+ (1,0) [0|255] ""  DCDC
 SG_ P2D_PrgData_Data7 : 56|8@1+ (1,0) [0|255] ""  DCDC

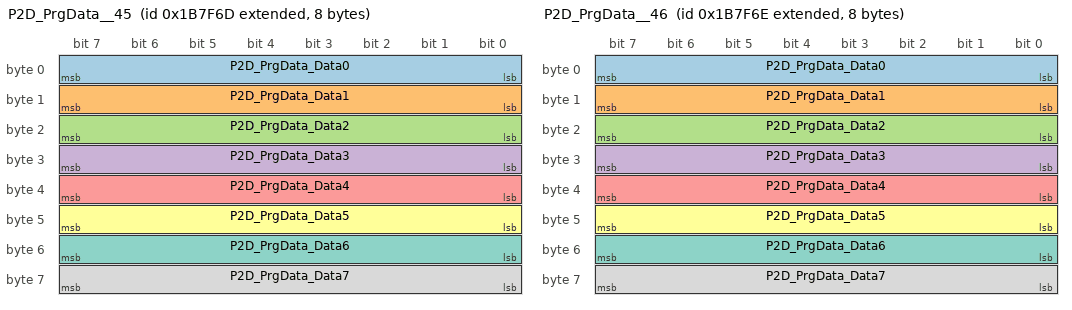
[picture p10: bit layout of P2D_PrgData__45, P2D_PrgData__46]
BO_ 2149285741 P2D_PrgData__45: 8 PC
 SG_ P2D_PrgData_Data0 : 0|8@1+ (1,0) [0|255] ""  DCDC
 SG_ P2D_PrgData_Data1 : 8|8@1+ (1,0) [0|255] ""  DCDC
 SG_ P2D_PrgData_Data2 : 16|8@1+ (1,0) [0|255] ""  DCDC
 SG_ P2D_PrgData_Data3 : 24|8@1+ (1,0) [0|255] ""  DCDC
 SG_ P2D_PrgData_Data4 : 32|8@1+ (1,0) [0|255] ""  DCDC
 SG_ P2D_PrgData_Data5 : 40|8@1+ (1,0) [0|255] ""  DCDC
 SG_ P2D_PrgData_Data6 : 48|8@1+ (1,0) [0|255] ""  DCDC
 SG_ P2D_PrgData_Data7 : 56|8@1+ (1,0) [0|255] ""  DCDC

BO_ 2149285742 P2D_PrgData__46: 8 PC
 SG_ P2D_PrgData_Data0 : 0|8@1+ (1,0) [0|255] ""  DCDC
 SG_ P2D_PrgData_Data1 : 8|8@1+ (1,0) [0|255] ""  DCDC
 SG_ P2D_PrgData_Data2 : 16|8@1+ (1,0) [0|255] ""  DCDC
 SG_ P2D_PrgData_Data3 : 24|8@1+ (1,0) [0|255] ""  DCDC
 SG_ P2D_PrgData_Data4 : 32|8@1+ (1,0) [0|255] ""  DCDC
 SG_ P2D_PrgData_Data5 : 40|8@1+ (1,0) [0|255] ""  DCDC
 SG_ P2D_PrgData_Data6 : 48|8@1+ (1,0) [0|255] ""  DCDC
 SG_ P2D_PrgData_Data7 : 56|8@1+ (1,0) [0|255] ""  DCDC

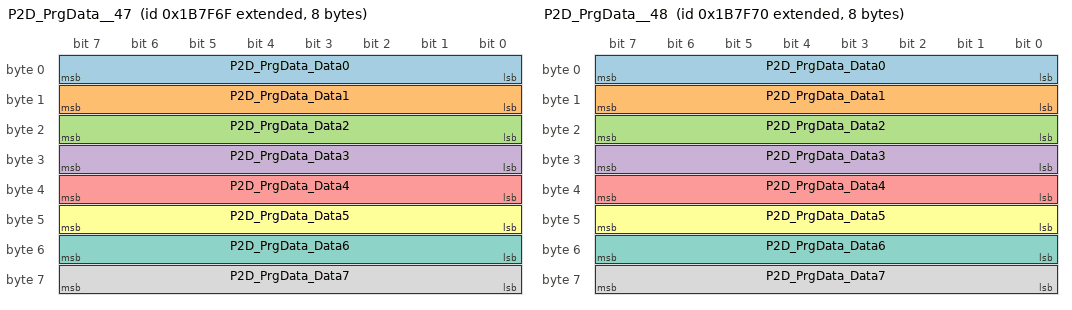
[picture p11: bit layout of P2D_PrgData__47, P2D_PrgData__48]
BO_ 2149285743 P2D_PrgData__47: 8 PC
 SG_ P2D_PrgData_Data0 : 0|8@1+ (1,0) [0|255] ""  DCDC
 SG_ P2D_PrgData_Data1 : 8|8@1+ (1,0) [0|255] ""  DCDC
 SG_ P2D_PrgData_Data2 : 16|8@1+ (1,0) [0|255] ""  DCDC
 SG_ P2D_PrgData_Data3 : 24|8@1+ (1,0) [0|255] ""  DCDC
 SG_ P2D_PrgData_Data4 : 32|8@1+ (1,0) [0|255] ""  DCDC
 SG_ P2D_PrgData_Data5 : 40|8@1+ (1,0) [0|255] ""  DCDC
 SG_ P2D_PrgData_Data6 : 48|8@1+ (1,0) [0|255] ""  DCDC
 SG_ P2D_PrgData_Data7 : 56|8@1+ (1,0) [0|255] ""  DCDC

BO_ 2149285744 P2D_PrgData__48: 8 PC
 SG_ P2D_PrgData_Data0 : 0|8@1+ (1,0) [0|255] ""  DCDC
 SG_ P2D_PrgData_Data1 : 8|8@1+ (1,0) [0|255] ""  DCDC
 SG_ P2D_PrgData_Data2 : 16|8@1+ (1,0) [0|255] ""  DCDC
 SG_ P2D_PrgData_Data3 : 24|8@1+ (1,0) [0|255] ""  DCDC
 SG_ P2D_PrgData_Data4 : 32|8@1+ (1,0) [0|255] ""  DCDC
 SG_ P2D_PrgData_Data5 : 40|8@1+ (1,0) [0|255] ""  DCDC
 SG_ P2D_PrgData_Data6 : 48|8@1+ (1,0) [0|255] ""  DCDC
 SG_ P2D_PrgData_Data7 : 56|8@1+ (1,0) [0|255] ""  DCDC

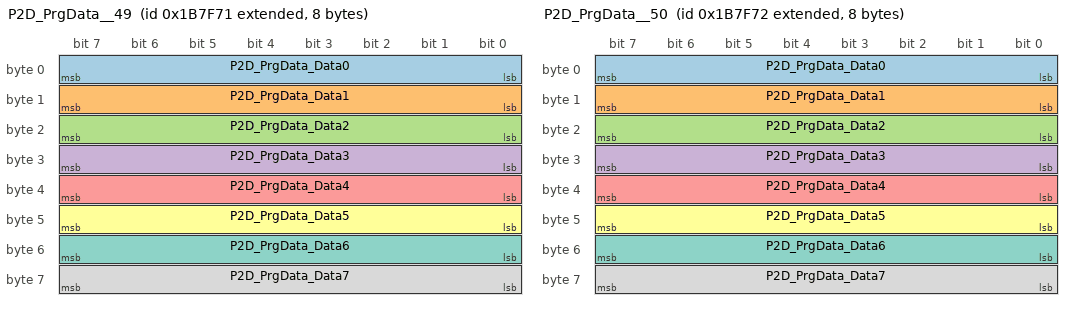
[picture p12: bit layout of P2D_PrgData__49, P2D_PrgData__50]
BO_ 2149285745 P2D_PrgData__49: 8 PC
 SG_ P2D_PrgData_Data0 : 0|8@1+ (1,0) [0|255] ""  DCDC
 SG_ P2D_PrgData_Data1 : 8|8@1+ (1,0) [0|255] ""  DCDC
 SG_ P2D_PrgData_Data2 : 16|8@1+ (1,0) [0|255] ""  DCDC
 SG_ P2D_PrgData_Data3 : 24|8@1+ (1,0) [0|255] ""  DCDC
 SG_ P2D_PrgData_Data4 : 32|8@1+ (1,0) [0|255] ""  DCDC
 SG_ P2D_PrgData_Data5 : 40|8@1+ (1,0) [0|255] ""  DCDC
 SG_ P2D_PrgData_Data6 : 48|8@1+ (1,0) [0|255] ""  DCDC
 SG_ P2D_PrgData_Data7 : 56|8@1+ (1,0) [0|255] ""  DCDC

BO_ 2149285746 P2D_PrgData__50: 8 PC
 SG_ P2D_PrgData_Data0 : 0|8@1+ (1,0) [0|255] ""  DCDC
 SG_ P2D_PrgData_Data1 : 8|8@1+ (1,0) [0|255] ""  DCDC
 SG_ P2D_PrgData_Data2 : 16|8@1+ (1,0) [0|255] ""  DCDC
 SG_ P2D_PrgData_Data3 : 24|8@1+ (1,0) [0|255] ""  DCDC
 SG_ P2D_PrgData_Data4 : 32|8@1+ (1,0) [0|255] ""  DCDC
 SG_ P2D_PrgData_Data5 : 40|8@1+ (1,0) [0|255] ""  DCDC
 SG_ P2D_PrgData_Data6 : 48|8@1+ (1,0) [0|255] ""  DCDC
 SG_ P2D_PrgData_Data7 : 56|8@1+ (1,0) [0|255] ""  DCDC

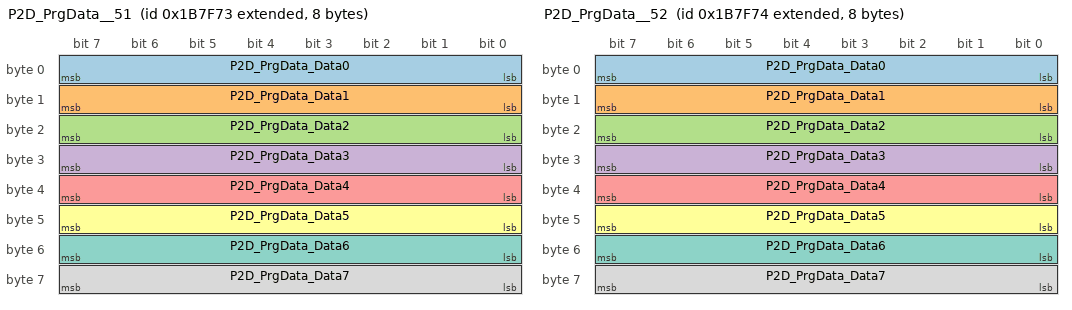
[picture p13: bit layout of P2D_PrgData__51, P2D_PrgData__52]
BO_ 2149285747 P2D_PrgData__51: 8 PC
 SG_ P2D_PrgData_Data0 : 0|8@1+ (1,0) [0|255] ""  DCDC
 SG_ P2D_PrgData_Data1 : 8|8@1+ (1,0) [0|255] ""  DCDC
 SG_ P2D_PrgData_Data2 : 16|8@1+ (1,0) [0|255] ""  DCDC
 SG_ P2D_PrgData_Data3 : 24|8@1+ (1,0) [0|255] ""  DCDC
 SG_ P2D_PrgData_Data4 : 32|8@1+ (1,0) [0|255] ""  DCDC
 SG_ P2D_PrgData_Data5 : 40|8@1+ (1,0) [0|255] ""  DCDC
 SG_ P2D_PrgData_Data6 : 48|8@1+ (1,0) [0|255] ""  DCDC
 SG_ P2D_PrgData_Data7 : 56|8@1+ (1,0) [0|255] ""  DCDC

BO_ 2149285748 P2D_PrgData__52: 8 PC
 SG_ P2D_PrgData_Data0 : 0|8@1+ (1,0) [0|255] ""  DCDC
 SG_ P2D_PrgData_Data1 : 8|8@1+ (1,0) [0|255] ""  DCDC
 SG_ P2D_PrgData_Data2 : 16|8@1+ (1,0) [0|255] ""  DCDC
 SG_ P2D_PrgData_Data3 : 24|8@1+ (1,0) [0|255] ""  DCDC
 SG_ P2D_PrgData_Data4 : 32|8@1+ (1,0) [0|255] ""  DCDC
 SG_ P2D_PrgData_Data5 : 40|8@1+ (1,0) [0|255] ""  DCDC
 SG_ P2D_PrgData_Data6 : 48|8@1+ (1,0) [0|255] ""  DCDC
 SG_ P2D_PrgData_Data7 : 56|8@1+ (1,0) [0|255] ""  DCDC

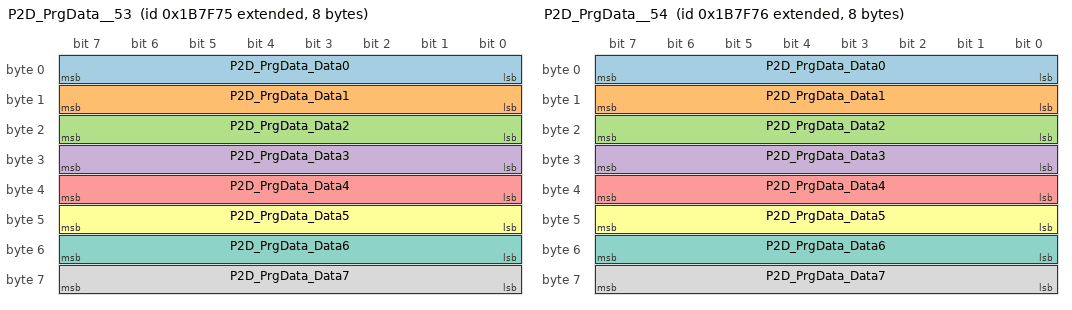
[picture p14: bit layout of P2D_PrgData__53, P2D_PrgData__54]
BO_ 2149285749 P2D_PrgData__53: 8 PC
 SG_ P2D_PrgData_Data0 : 0|8@1+ (1,0) [0|255] ""  DCDC
 SG_ P2D_PrgData_Data1 : 8|8@1+ (1,0) [0|255] ""  DCDC
 SG_ P2D_PrgData_Data2 : 16|8@1+ (1,0) [0|255] ""  DCDC
 SG_ P2D_PrgData_Data3 : 24|8@1+ (1,0) [0|255] ""  DCDC
 SG_ P2D_PrgData_Data4 : 32|8@1+ (1,0) [0|255] ""  DCDC
 SG_ P2D_PrgData_Data5 : 40|8@1+ (1,0) [0|255] ""  DCDC
 SG_ P2D_PrgData_Data6 : 48|8@1+ (1,0) [0|255] ""  DCDC
 SG_ P2D_PrgData_Data7 : 56|8@1+ (1,0) [0|255] ""  DCDC

BO_ 2149285750 P2D_PrgData__54: 8 PC
 SG_ P2D_PrgData_Data0 : 0|8@1+ (1,0) [0|255] ""  DCDC
 SG_ P2D_PrgData_Data1 : 8|8@1+ (1,0) [0|255] ""  DCDC
 SG_ P2D_PrgData_Data2 : 16|8@1+ (1,0) [0|255] ""  DCDC
 SG_ P2D_PrgData_Data3 : 24|8@1+ (1,0) [0|255] ""  DCDC
 SG_ P2D_PrgData_Data4 : 32|8@1+ (1,0) [0|255] ""  DCDC
 SG_ P2D_PrgData_Data5 : 40|8@1+ (1,0) [0|255] ""  DCDC
 SG_ P2D_PrgData_Data6 : 48|8@1+ (1,0) [0|255] ""  DCDC
 SG_ P2D_PrgData_Data7 : 56|8@1+ (1,0) [0|255] ""  DCDC

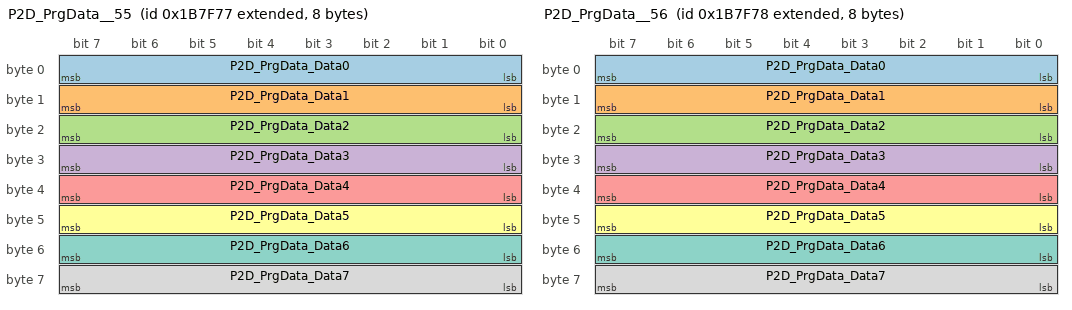
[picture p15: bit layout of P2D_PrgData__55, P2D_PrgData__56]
BO_ 2149285751 P2D_PrgData__55: 8 PC
 SG_ P2D_PrgData_Data0 : 0|8@1+ (1,0) [0|255] ""  DCDC
 SG_ P2D_PrgData_Data1 : 8|8@1+ (1,0) [0|255] ""  DCDC
 SG_ P2D_PrgData_Data2 : 16|8@1+ (1,0) [0|255] ""  DCDC
 SG_ P2D_PrgData_Data3 : 24|8@1+ (1,0) [0|255] ""  DCDC
 SG_ P2D_PrgData_Data4 : 32|8@1+ (1,0) [0|255] ""  DCDC
 SG_ P2D_PrgData_Data5 : 40|8@1+ (1,0) [0|255] ""  DCDC
 SG_ P2D_PrgData_Data6 : 48|8@1+ (1,0) [0|255] ""  DCDC
 SG_ P2D_PrgData_Data7 : 56|8@1+ (1,0) [0|255] ""  DCDC

BO_ 2149285752 P2D_PrgData__56: 8 PC
 SG_ P2D_PrgData_Data0 : 0|8@1+ (1,0) [0|255] ""  DCDC
 SG_ P2D_PrgData_Data1 : 8|8@1+ (1,0) [0|255] ""  DCDC
 SG_ P2D_PrgData_Data2 : 16|8@1+ (1,0) [0|255] ""  DCDC
 SG_ P2D_PrgData_Data3 : 24|8@1+ (1,0) [0|255] ""  DCDC
 SG_ P2D_PrgData_Data4 : 32|8@1+ (1,0) [0|255] ""  DCDC
 SG_ P2D_PrgData_Data5 : 40|8@1+ (1,0) [0|255] ""  DCDC
 SG_ P2D_PrgData_Data6 : 48|8@1+ (1,0) [0|255] ""  DCDC
 SG_ P2D_PrgData_Data7 : 56|8@1+ (1,0) [0|255] ""  DCDC

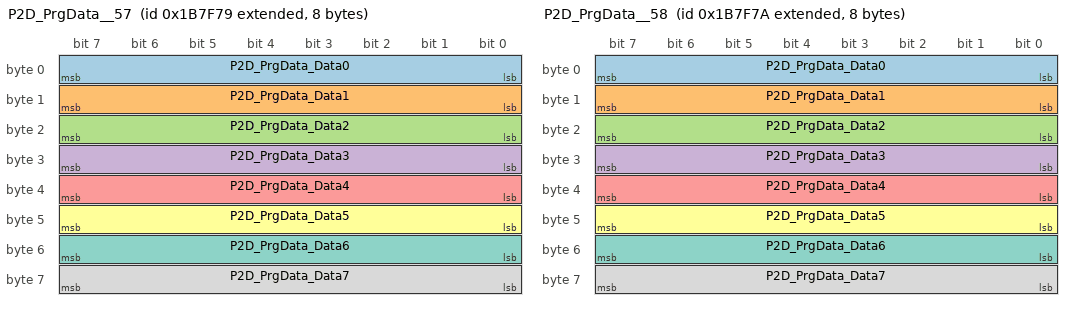
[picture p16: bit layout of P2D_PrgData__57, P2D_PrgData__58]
BO_ 2149285753 P2D_PrgData__57: 8 PC
 SG_ P2D_PrgData_Data0 : 0|8@1+ (1,0) [0|255] ""  DCDC
 SG_ P2D_PrgData_Data1 : 8|8@1+ (1,0) [0|255] ""  DCDC
 SG_ P2D_PrgData_Data2 : 16|8@1+ (1,0) [0|255] ""  DCDC
 SG_ P2D_PrgData_Data3 : 24|8@1+ (1,0) [0|255] ""  DCDC
 SG_ P2D_PrgData_Data4 : 32|8@1+ (1,0) [0|255] ""  DCDC
 SG_ P2D_PrgData_Data5 : 40|8@1+ (1,0) [0|255] ""  DCDC
 SG_ P2D_PrgData_Data6 : 48|8@1+ (1,0) [0|255] ""  DCDC
 SG_ P2D_PrgData_Data7 : 56|8@1+ (1,0) [0|255] ""  DCDC

BO_ 2149285754 P2D_PrgData__58: 8 PC
 SG_ P2D_PrgData_Data0 : 0|8@1+ (1,0) [0|255] ""  DCDC
 SG_ P2D_PrgData_Data1 : 8|8@1+ (1,0) [0|255] ""  DCDC
 SG_ P2D_PrgData_Data2 : 16|8@1+ (1,0) [0|255] ""  DCDC
 SG_ P2D_PrgData_Data3 : 24|8@1+ (1,0) [0|255] ""  DCDC
 SG_ P2D_PrgData_Data4 : 32|8@1+ (1,0) [0|255] ""  DCDC
 SG_ P2D_PrgData_Data5 : 40|8@1+ (1,0) [0|255] ""  DCDC
 SG_ P2D_PrgData_Data6 : 48|8@1+ (1,0) [0|255] ""  DCDC
 SG_ P2D_PrgData_Data7 : 56|8@1+ (1,0) [0|255] ""  DCDC

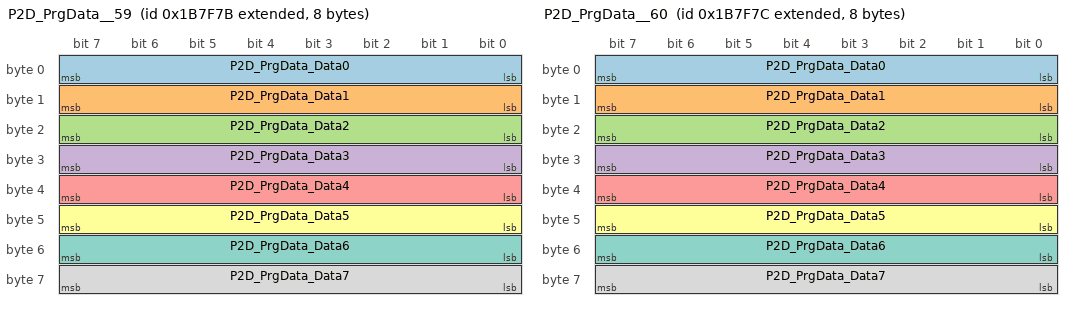
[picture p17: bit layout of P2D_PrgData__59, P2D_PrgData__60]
BO_ 2149285755 P2D_PrgData__59: 8 PC
 SG_ P2D_PrgData_Data0 : 0|8@1+ (1,0) [0|255] ""  DCDC
 SG_ P2D_PrgData_Data1 : 8|8@1+ (1,0) [0|255] ""  DCDC
 SG_ P2D_PrgData_Data2 : 16|8@1+ (1,0) [0|255] ""  DCDC
 SG_ P2D_PrgData_Data3 : 24|8@1+ (1,0) [0|255] ""  DCDC
 SG_ P2D_PrgData_Data4 : 32|8@1+ (1,0) [0|255] ""  DCDC
 SG_ P2D_PrgData_Data5 : 40|8@1+ (1,0) [0|255] ""  DCDC
 SG_ P2D_PrgData_Data6 : 48|8@1+ (1,0) [0|255] ""  DCDC
 SG_ P2D_PrgData_Data7 : 56|8@1+ (1,0) [0|255] ""  DCDC

BO_ 2149285756 P2D_PrgData__60: 8 PC
 SG_ P2D_PrgData_Data0 : 0|8@1+ (1,0) [0|255] ""  DCDC
 SG_ P2D_PrgData_Data1 : 8|8@1+ (1,0) [0|255] ""  DCDC
 SG_ P2D_PrgData_Data2 : 16|8@1+ (1,0) [0|255] ""  DCDC
 SG_ P2D_PrgData_Data3 : 24|8@1+ (1,0) [0|255] ""  DCDC
 SG_ P2D_PrgData_Data4 : 32|8@1+ (1,0) [0|255] ""  DCDC
 SG_ P2D_PrgData_Data5 : 40|8@1+ (1,0) [0|255] ""  DCDC
 SG_ P2D_PrgData_Data6 : 48|8@1+ (1,0) [0|255] ""  DCDC
 SG_ P2D_PrgData_Data7 : 56|8@1+ (1,0) [0|255] ""  DCDC

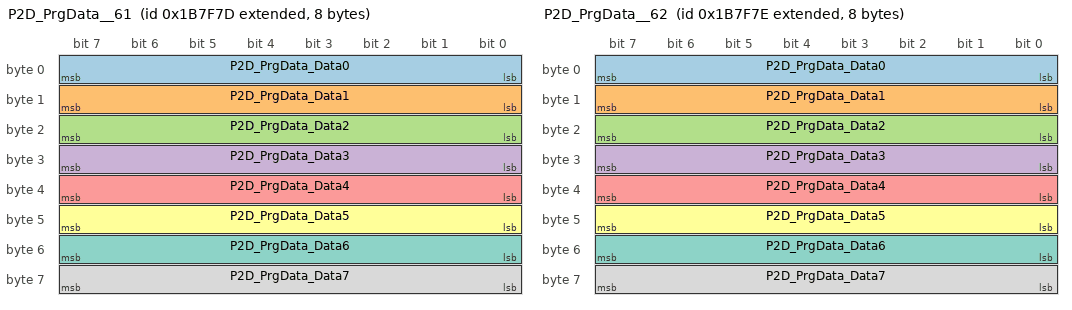
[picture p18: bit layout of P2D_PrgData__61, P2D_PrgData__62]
BO_ 2149285757 P2D_PrgData__61: 8 PC
 SG_ P2D_PrgData_Data0 : 0|8@1+ (1,0) [0|255] ""  DCDC
 SG_ P2D_PrgData_Data1 : 8|8@1+ (1,0) [0|255] ""  DCDC
 SG_ P2D_PrgData_Data2 : 16|8@1+ (1,0) [0|255] ""  DCDC
 SG_ P2D_PrgData_Data3 : 24|8@1+ (1,0) [0|255] ""  DCDC
 SG_ P2D_PrgData_Data4 : 32|8@1+ (1,0) [0|255] ""  DCDC
 SG_ P2D_PrgData_Data5 : 40|8@1+ (1,0) [0|255] ""  DCDC
 SG_ P2D_PrgData_Data6 : 48|8@1+ (1,0) [0|255] ""  DCDC
 SG_ P2D_PrgData_Data7 : 56|8@1+ (1,0) [0|255] ""  DCDC

BO_ 2149285758 P2D_PrgData__62: 8 PC
 SG_ P2D_PrgData_Data0 : 0|8@1+ (1,0) [0|255] ""  DCDC
 SG_ P2D_PrgData_Data1 : 8|8@1+ (1,0) [0|255] ""  DCDC
 SG_ P2D_PrgData_Data2 : 16|8@1+ (1,0) [0|255] ""  DCDC
 SG_ P2D_PrgData_Data3 : 24|8@1+ (1,0) [0|255] ""  DCDC
 SG_ P2D_PrgData_Data4 : 32|8@1+ (1,0) [0|255] ""  DCDC
 SG_ P2D_PrgData_Data5 : 40|8@1+ (1,0) [0|255] ""  DCDC
 SG_ P2D_PrgData_Data6 : 48|8@1+ (1,0) [0|255] ""  DCDC
 SG_ P2D_PrgData_Data7 : 56|8@1+ (1,0) [0|255] ""  DCDC

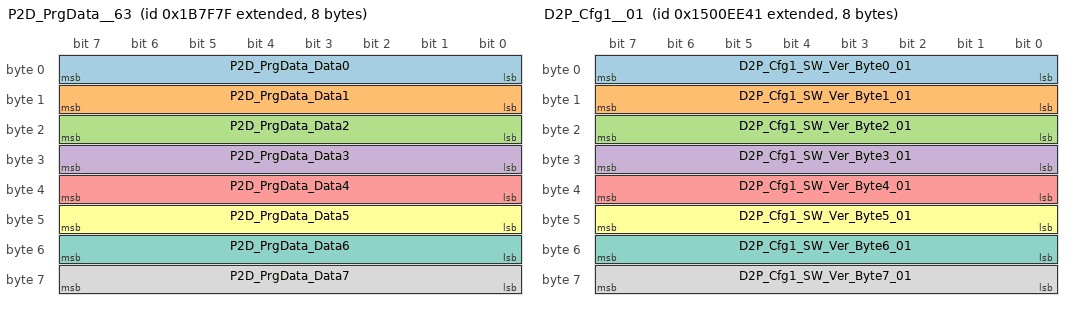
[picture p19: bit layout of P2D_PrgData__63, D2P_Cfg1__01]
BO_ 2149285759 P2D_PrgData__63: 8 PC
 SG_ P2D_PrgData_Data0 : 0|8@1+ (1,0) [0|255] ""  DCDC
 SG_ P2D_PrgData_Data1 : 8|8@1+ (1,0) [0|255] ""  DCDC
 SG_ P2D_PrgData_Data2 : 16|8@1+ (1,0) [0|255] ""  DCDC
 SG_ P2D_PrgData_Data3 : 24|8@1+ (1,0) [0|255] ""  DCDC
 SG_ P2D_PrgData_Data4 : 32|8@1+ (1,0) [0|255] ""  DCDC
 SG_ P2D_PrgData_Data5 : 40|8@1+ (1,0) [0|255] ""  DCDC
 SG_ P2D_PrgData_Data6 : 48|8@1+ (1,0) [0|255] ""  DCDC
 SG_ P2D_PrgData_Data7 : 56|8@1+ (1,0) [0|255] ""  DCDC

BO_ 2499866177 D2P_Cfg1__01: 8 DCDC
 SG_ D2P_Cfg1_SW_Ver_Byte0_01 : 0|8@1+ (1,0) [0|255] ""  PC
 SG_ D2P_Cfg1_SW_Ver_Byte1_01 : 8|8@1+ (1,0) [0|255] ""  PC
 SG_ D2P_Cfg1_SW_Ver_Byte2_01 : 16|8@1+ (1,0) [0|255] ""  PC
 SG_ D2P_Cfg1_SW_Ver_Byte3_01 : 24|8@1+ (1,0) [0|255] ""  PC
 SG_ D2P_Cfg1_SW_Ver_Byte4_01 : 32|8@1+ (1,0) [0|255] ""  PC
 SG_ D2P_Cfg1_SW_Ver_Byte5_01 : 40|8@1+ (1,0) [0|255] ""  PC
 SG_ D2P_Cfg1_SW_Ver_Byte6_01 : 48|8@1+ (1,0) [0|255] ""  PC
 SG_ D2P_Cfg1_SW_Ver_Byte7_01 : 56|8@1+ (1,0) [0|255] ""  PC

BO_ 2499866178 D2P_Cfg1__02: 8 DCDC
 SG_ D2P_Cfg1_SW_Ver_Byte0_02 : 0|8@1+ (1,0) [0|255] ""  PC
 SG_ D2P_Cfg1_SW_Ver_Byte1_02 : 8|8@1+ (1,0) [0|255] ""  PC
 SG_ D2P_Cfg1_SW_Ver_Byte2_02 : 16|8@1+ (1,0) [0|255] ""  PC
 SG_ D2P_Cfg1_SW_Ver_Byte3_02 : 24|8@1+ (1,0) [0|255] ""  PC
 SG_ D2P_Cfg1_SW_Ver_Byte4_02 : 32|8@1+ (1,0) [0|255] ""  PC
 SG_ D2P_Cfg1_SW_Ver_Byte5_02 : 40|8@1+ (1,0) [0|255] ""  PC
 SG_ D2P_Cfg1_SW_Ver_Byte6_02 : 48|8@1+ (1,0) [0|255] ""  PC
 SG_ D2P_Cfg1_SW_Ver_Byte7_02 : 56|8@1+ (1,0) [0|255] ""  PC

BO_ 2499866179 D2P_Cfg1__03: 8 DCDC
 SG_ D2P_Cfg1_SW_Ver_Byte0_03 : 0|8@1+ (1,0) [0|255] ""  PC
 SG_ D2P_Cfg1_SW_Ver_Byte1_03 : 8|8@1+ (1,0) [0|255] ""  PC
 SG_ D2P_Cfg1_SW_Ver_Byte2_03 : 16|8@1+ (1,0) [0|255] ""  PC
 SG_ D2P_Cfg1_SW_Ver_Byte3_03 : 24|8@1+ (1,0) [0|255] ""  PC
 SG_ D2P_Cfg1_SW_Ver_Byte4_03 : 32|8@1+ (1,0) [0|255] ""  PC
 SG_ D2P_Cfg1_SW_Ver_Byte5_03 : 40|8@1+ (1,0) [0|255] ""  PC
 SG_ D2P_Cfg1_SW_Ver_Byte6_03 : 48|8@1+ (1,0) [0|255] ""  PC
 SG_ D2P_Cfg1_SW_Ver_Byte7_03 : 56|8@1+ (1,0) [0|255] ""  PC

BO_ 2499866180 D2P_Cfg1__04: 8 DCDC
 SG_ D2P_Cfg1_SW_Ver_Byte0_04 : 0|8@1+ (1,0) [0|255] ""  PC
 SG_ D2P_Cfg1_SW_Ver_Byte1_04 : 8|8@1+ (1,0) [0|255] ""  PC
 SG_ D2P_Cfg1_SW_Ver_Byte2_04 : 16|8@1+ (1,0) [0|255] ""  PC
 SG_ D2P_Cfg1_SW_Ver_Byte3_04 : 24|8@1+ (1,0) [0|255] ""  PC
 SG_ D2P_Cfg1_SW_Ver_Byte4_04 : 32|8@1+ (1,0) [0|255] ""  PC
 SG_ D2P_Cfg1_SW_Ver_Byte5_04 : 40|8@1+ (1,0) [0|255] ""  PC
 SG_ D2P_Cfg1_SW_Ver_Byte6_04 : 48|8@1+ (1,0) [0|255] ""  PC
 SG_ D2P_Cfg1_SW_Ver_Byte7_04 : 56|8@1+ (1,0) [0|255] ""  PC

BO_ 2499866181 D2P_Cfg1__05: 8 DCDC
 SG_ D2P_Cfg1_SW_Ver_Byte0_05 : 0|8@1+ (1,0) [0|255] ""  PC
 SG_ D2P_Cfg1_SW_Ver_Byte1_05 : 8|8@1+ (1,0) [0|255] ""  PC
 SG_ D2P_Cfg1_SW_Ver_Byte2_05 : 16|8@1+ (1,0) [0|255] ""  PC
 SG_ D2P_Cfg1_SW_Ver_Byte3_05 : 24|8@1+ (1,0) [0|255] ""  PC
 SG_ D2P_Cfg1_SW_Ver_Byte4_05 : 32|8@1+ (1,0) [0|255] ""  PC
 SG_ D2P_Cfg1_SW_Ver_Byte5_05 : 40|8@1+ (1,0) [0|255] ""  PC
 SG_ D2P_Cfg1_SW_Ver_Byte6_05 : 48|8@1+ (1,0) [0|255] ""  PC
 SG_ D2P_Cfg1_SW_Ver_Byte7_05 : 56|8@1+ (1,0) [0|255] ""  PC

BO_ 2499866182 D2P_Cfg1__06: 8 DCDC
 SG_ D2P_Cfg1_SW_Ver_Byte0_06 : 0|8@1+ (1,0) [0|255] ""  PC
 SG_ D2P_Cfg1_SW_Ver_Byte1_06 : 8|8@1+ (1,0) [0|255] ""  PC
 SG_ D2P_Cfg1_SW_Ver_Byte2_06 : 16|8@1+ (1,0) [0|255] ""  PC
 SG_ D2P_Cfg1_SW_Ver_Byte3_06 : 24|8@1+ (1,0) [0|255] ""  PC
 SG_ D2P_Cfg1_SW_Ver_Byte4_06 : 32|8@1+ (1,0) [0|255] ""  PC
 SG_ D2P_Cfg1_SW_Ver_Byte5_06 : 40|8@1+ (1,0) [0|255] ""  PC
 SG_ D2P_Cfg1_SW_Ver_Byte6_06 : 48|8@1+ (1,0) [0|255] ""  PC
 SG_ D2P_Cfg1_SW_Ver_Byte7_06 : 56|8@1+ (1,0) [0|255] ""  PC

BO_ 2499866183 D2P_Cfg1__07: 8 DCDC
 SG_ D2P_Cfg1_SW_Ver_Byte0_07 : 0|8@1+ (1,0) [0|255] ""  PC
 SG_ D2P_Cfg1_SW_Ver_Byte1_07 : 8|8@1+ (1,0) [0|255] ""  PC
 SG_ D2P_Cfg1_SW_Ver_Byte2_07 : 16|8@1+ (1,0) [0|255] ""  PC
 SG_ D2P_Cfg1_SW_Ver_Byte3_07 : 24|8@1+ (1,0) [0|255] ""  PC
 SG_ D2P_Cfg1_SW_Ver_Byte4_07 : 32|8@1+ (1,0) [0|255] ""  PC
 SG_ D2P_Cfg1_SW_Ver_Byte5_07 : 40|8@1+ (1,0) [0|255] ""  PC
 SG_ D2P_Cfg1_SW_Ver_Byte6_07 : 48|8@1+ (1,0) [0|255] ""  PC
 SG_ D2P_Cfg1_SW_Ver_Byte7_07 : 56|8@1+ (1,0) [0|255] ""  PC

BO_ 2499866184 D2P_Cfg1__08: 8 DCDC
 SG_ D2P_Cfg1_SW_Ver_Byte0_08 : 0|8@1+ (1,0) [0|255] ""  PC
 SG_ D2P_Cfg1_SW_Ver_Byte1_08 : 8|8@1+ (1,0) [0|255] ""  PC
 SG_ D2P_Cfg1_SW_Ver_Byte2_08 : 16|8@1+ (1,0) [0|255] ""  PC
 SG_ D2P_Cfg1_SW_Ver_Byte3_08 : 24|8@1+ (1,0) [0|255] ""  PC
 SG_ D2P_Cfg1_SW_Ver_Byte4_08 : 32|8@1+ (1,0) [0|255] ""  PC
 SG_ D2P_Cfg1_SW_Ver_Byte5_08 : 40|8@1+ (1,0) [0|255] ""  PC
 SG_ D2P_Cfg1_SW_Ver_Byte6_08 : 48|8@1+ (1,0) [0|255] ""  PC
 SG_ D2P_Cfg1_SW_Ver_Byte7_08 : 56|8@1+ (1,0) [0|255] ""  PC

BO_ 2499866185 D2P_Cfg1__09: 8 DCDC
 SG_ D2P_Cfg1_SW_Ver_Byte0_09 : 0|8@1+ (1,0) [0|255] ""  PC
 SG_ D2P_Cfg1_SW_Ver_Byte1_09 : 8|8@1+ (1,0) [0|255] ""  PC
 SG_ D2P_Cfg1_SW_Ver_Byte2_09 : 16|8@1+ (1,0) [0|255] ""  PC
 SG_ D2P_Cfg1_SW_Ver_Byte3_09 : 24|8@1+ (1,0) [0|255] ""  PC
 SG_ D2P_Cfg1_SW_Ver_Byte4_09 : 32|8@1+ (1,0) [0|255] ""  PC
 SG_ D2P_Cfg1_SW_Ver_Byte5_09 : 40|8@1+ (1,0) [0|255] ""  PC
 SG_ D2P_Cfg1_SW_Ver_Byte6_09 : 48|8@1+ (1,0) [0|255] ""  PC
 SG_ D2P_Cfg1_SW_Ver_Byte7_09 : 56|8@1+ (1,0) [0|255] ""  PC

BO_ 2499866186 D2P_Cfg1__10: 8 DCDC
 SG_ D2P_Cfg1_SW_Ver_Byte0_10 : 0|8@1+ (1,0) [0|255] ""  PC
 SG_ D2P_Cfg1_SW_Ver_Byte1_10 : 8|8@1+ (1,0) [0|255] ""  PC
 SG_ D2P_Cfg1_SW_Ver_Byte2_10 : 16|8@1+ (1,0) [0|255] ""  PC
 SG_ D2P_Cfg1_SW_Ver_Byte3_10 : 24|8@1+ (1,0) [0|255] ""  PC
 SG_ D2P_Cfg1_SW_Ver_Byte4_10 : 32|8@1+ (1,0) [0|255] ""  PC
 SG_ D2P_Cfg1_SW_Ver_Byte5_10 : 40|8@1+ (1,0) [0|255] ""  PC
 SG_ D2P_Cfg1_SW_Ver_Byte6_10 : 48|8@1+ (1,0) [0|255] ""  PC
 SG_ D2P_Cfg1_SW_Ver_Byte7_10 : 56|8@1+ (1,0) [0|255] ""  PC

BO_ 2499866187 D2P_Cfg1__11: 8 DCDC
 SG_ D2P_Cfg1_SW_Ver_Byte0_11 : 0|8@1+ (1,0) [0|255] ""  PC
 SG_ D2P_Cfg1_SW_Ver_Byte1_11 : 8|8@1+ (1,0) [0|255] ""  PC
 SG_ D2P_Cfg1_SW_Ver_Byte2_11 : 16|8@1+ (1,0) [0|255] ""  PC
 SG_ D2P_Cfg1_SW_Ver_Byte3_11 : 24|8@1+ (1,0) [0|255] ""  PC
 SG_ D2P_Cfg1_SW_Ver_Byte4_11 : 32|8@1+ (1,0) [0|255] ""  PC
 SG_ D2P_Cfg1_SW_Ver_Byte5_11 : 40|8@1+ (1,0) [0|255] ""  PC
 SG_ D2P_Cfg1_SW_Ver_Byte6_11 : 48|8@1+ (1,0) [0|255] ""  PC
 SG_ D2P_Cfg1_SW_Ver_Byte7_11 : 56|8@1+ (1,0) [0|255] ""  PC

BO_ 2499866188 D2P_Cfg1__12: 8 DCDC
 SG_ D2P_Cfg1_SW_Ver_Byte0_12 : 0|8@1+ (1,0) [0|255] ""  PC
 SG_ D2P_Cfg1_SW_Ver_Byte1_12 : 8|8@1+ (1,0) [0|255] ""  PC
 SG_ D2P_Cfg1_SW_Ver_Byte2_12 : 16|8@1+ (1,0) [0|255] ""  PC
 SG_ D2P_Cfg1_SW_Ver_Byte3_12 : 24|8@1+ (1,0) [0|255] ""  PC
 SG_ D2P_Cfg1_SW_Ver_Byte4_12 : 32|8@1+ (1,0) [0|255] ""  PC
 SG_ D2P_Cfg1_SW_Ver_Byte5_12 : 40|8@1+ (1,0) [0|255] ""  PC
 SG_ D2P_Cfg1_SW_Ver_Byte6_12 : 48|8@1+ (1,0) [0|255] ""  PC
 SG_ D2P_Cfg1_SW_Ver_Byte7_12 : 56|8@1+ (1,0) [0|255] ""  PC

BO_ 2499866189 D2P_Cfg1__13: 8 DCDC
 SG_ D2P_Cfg1_SW_Ver_Byte0_13 : 0|8@1+ (1,0) [0|255] ""  PC
 SG_ D2P_Cfg1_SW_Ver_Byte1_13 : 8|8@1+ (1,0) [0|255] ""  PC
 SG_ D2P_Cfg1_SW_Ver_Byte2_13 : 16|8@1+ (1,0) [0|255] ""  PC
 SG_ D2P_Cfg1_SW_Ver_Byte3_13 : 24|8@1+ (1,0) [0|255] ""  PC
 SG_ D2P_Cfg1_SW_Ver_Byte4_13 : 32|8@1+ (1,0) [0|255] ""  PC
 SG_ D2P_Cfg1_SW_Ver_Byte5_13 : 40|8@1+ (1,0) [0|255] ""  PC
 SG_ D2P_Cfg1_SW_Ver_Byte6_13 : 48|8@1+ (1,0) [0|255] ""  PC
 SG_ D2P_Cfg1_SW_Ver_Byte7_13 : 56|8@1+ (1,0) [0|255] ""  PC

BO_ 2499866190 D2P_Cfg1__14: 8 DCDC
 SG_ D2P_Cfg1_SW_Ver_Byte0_14 : 0|8@1+ (1,0) [0|255] ""  PC
 SG_ D2P_Cfg1_SW_Ver_Byte1_14 : 8|8@1+ (1,0) [0|255] ""  PC
 SG_ D2P_Cfg1_SW_Ver_Byte2_14 : 16|8@1+ (1,0) [0|255] ""  PC
 SG_ D2P_Cfg1_SW_Ver_Byte3_14 : 24|8@1+ (1,0) [0|255] ""  PC
 SG_ D2P_Cfg1_SW_Ver_Byte4_14 : 32|8@1+ (1,0) [0|255] ""  PC
 SG_ D2P_Cfg1_SW_Ver_Byte5_14 : 40|8@1+ (1,0) [0|255] ""  PC
 SG_ D2P_Cfg1_SW_Ver_Byte6_14 : 48|8@1+ (1,0) [0|255] ""  PC
 SG_ D2P_Cfg1_SW_Ver_Byte7_14 : 56|8@1+ (1,0) [0|255] ""  PC

BO_ 2499866191 D2P_Cfg1__15: 8 DCDC
 SG_ D2P_Cfg1_SW_Ver_Byte0_15 : 0|8@1+ (1,0) [0|255] ""  PC
 SG_ D2P_Cfg1_SW_Ver_Byte1_15 : 8|8@1+ (1,0) [0|255] ""  PC
 SG_ D2P_Cfg1_SW_Ver_Byte2_15 : 16|8@1+ (1,0) [0|255] ""  PC
 SG_ D2P_Cfg1_SW_Ver_Byte3_15 : 24|8@1+ (1,0) [0|255] ""  PC
 SG_ D2P_Cfg1_SW_Ver_Byte4_15 : 32|8@1+ (1,0) [0|255] ""  PC
 SG_ D2P_Cfg1_SW_Ver_Byte5_15 : 40|8@1+ (1,0) [0|255] ""  PC
 SG_ D2P_Cfg1_SW_Ver_Byte6_15 : 48|8@1+ (1,0) [0|255] ""  PC
 SG_ D2P_Cfg1_SW_Ver_Byte7_15 : 56|8@1+ (1,0) [0|255] ""  PC

BO_ 2499866192 D2P_Cfg1__16: 8 DCDC
 SG_ D2P_Cfg1_SW_Ver_Byte0_16 : 0|8@1+ (1,0) [0|255] ""  PC
 SG_ D2P_Cfg1_SW_Ver_Byte1_16 : 8|8@1+ (1,0) [0|255] ""  PC
 SG_ D2P_Cfg1_SW_Ver_Byte2_16 : 16|8@1+ (1,0) [0|255] ""  PC
 SG_ D2P_Cfg1_SW_Ver_Byte3_16 : 24|8@1+ (1,0) [0|255] ""  PC
 SG_ D2P_Cfg1_SW_Ver_Byte4_16 : 32|8@1+ (1,0) [0|255] ""  PC
 SG_ D2P_Cfg1_SW_Ver_Byte5_16 : 40|8@1+ (1,0) [0|255] ""  PC
 SG_ D2P_Cfg1_SW_Ver_Byte6_16 : 48|8@1+ (1,0) [0|255] ""  PC
 SG_ D2P_Cfg1_SW_Ver_Byte7_16 : 56|8@1+ (1,0) [0|255] ""  PC

BO_ 2499866193 D2P_Cfg1__17: 8 DCDC
 SG_ D2P_Cfg1_SW_Ver_Byte0_17 : 0|8@1+ (1,0) [0|255] ""  PC
 SG_ D2P_Cfg1_SW_Ver_Byte1_17 : 8|8@1+ (1,0) [0|255] ""  PC
 SG_ D2P_Cfg1_SW_Ver_Byte2_17 : 16|8@1+ (1,0) [0|255] ""  PC
 SG_ D2P_Cfg1_SW_Ver_Byte3_17 : 24|8@1+ (1,0) [0|255] ""  PC
 SG_ D2P_Cfg1_SW_Ver_Byte4_17 : 32|8@1+ (1,0) [0|255] ""  PC
 SG_ D2P_Cfg1_SW_Ver_Byte5_17 : 40|8@1+ (1,0) [0|255] ""  PC
 SG_ D2P_Cfg1_SW_Ver_Byte6_17 : 48|8@1+ (1,0) [0|255] ""  PC
 SG_ D2P_Cfg1_SW_Ver_Byte7_17 : 56|8@1+ (1,0) [0|255] ""  PC

BO_ 2499866194 D2P_Cfg1__18: 8 DCDC
 SG_ D2P_Cfg1_SW_Ver_Byte0_18 : 0|8@1+ (1,0) [0|255] ""  PC
 SG_ D2P_Cfg1_SW_Ver_Byte1_18 : 8|8@1+ (1,0) [0|255] ""  PC
 SG_ D2P_Cfg1_SW_Ver_Byte2_18 : 16|8@1+ (1,0) [0|255] ""  PC
 SG_ D2P_Cfg1_SW_Ver_Byte3_18 : 24|8@1+ (1,0) [0|255] ""  PC
 SG_ D2P_Cfg1_SW_Ver_Byte4_18 : 32|8@1+ (1,0) [0|255] ""  PC
 SG_ D2P_Cfg1_SW_Ver_Byte5_18 : 40|8@1+ (1,0) [0|255] ""  PC
 SG_ D2P_Cfg1_SW_Ver_Byte6_18 : 48|8@1+ (1,0) [0|255] ""  PC
 SG_ D2P_Cfg1_SW_Ver_Byte7_18 : 56|8@1+ (1,0) [0|255] ""  PC

BO_ 2499866195 D2P_Cfg1__19: 8 DCDC
 SG_ D2P_Cfg1_SW_Ver_Byte0_19 : 0|8@1+ (1,0) [0|255] ""  PC
 SG_ D2P_Cfg1_SW_Ver_Byte1_19 : 8|8@1+ (1,0) [0|255] ""  PC
 SG_ D2P_Cfg1_SW_Ver_Byte2_19 : 16|8@1+ (1,0) [0|255] ""  PC
 SG_ D2P_Cfg1_SW_Ver_Byte3_19 : 24|8@1+ (1,0) [0|255] ""  PC
 SG_ D2P_Cfg1_SW_Ver_Byte4_19 : 32|8@1+ (1,0) [0|255] ""  PC
 SG_ D2P_Cfg1_SW_Ver_Byte5_19 : 40|8@1+ (1,0) [0|255] ""  PC
 SG_ D2P_Cfg1_SW_Ver_Byte6_19 : 48|8@1+ (1,0) [0|255] ""  PC
 SG_ D2P_Cfg1_SW_Ver_Byte7_19 : 56|8@1+ (1,0) [0|255] ""  PC

BO_ 2499866196 D2P_Cfg1__20: 8 DCDC
 SG_ D2P_Cfg1_SW_Ver_Byte0_20 : 0|8@1+ (1,0) [0|255] ""  PC
 SG_ D2P_Cfg1_SW_Ver_Byte1_20 : 8|8@1+ (1,0) [0|255] ""  PC
 SG_ D2P_Cfg1_SW_Ver_Byte2_20 : 16|8@1+ (1,0) [0|255] ""  PC
 SG_ D2P_Cfg1_SW_Ver_Byte3_20 : 24|8@1+ (1,0) [0|255] ""  PC
 SG_ D2P_Cfg1_SW_Ver_Byte4_20 : 32|8@1+ (1,0) [0|255] ""  PC
 SG_ D2P_Cfg1_SW_Ver_Byte5_20 : 40|8@1+ (1,0) [0|255] ""  PC
 SG_ D2P_Cfg1_SW_Ver_Byte6_20 : 48|8@1+ (1,0) [0|255] ""  PC
 SG_ D2P_Cfg1_SW_Ver_Byte7_20 : 56|8@1+ (1,0) [0|255] ""  PC

BO_ 2499866197 D2P_Cfg1__21: 8 DCDC
 SG_ D2P_Cfg1_SW_Ver_Byte0_21 : 0|8@1+ (1,0) [0|255] ""  PC
 SG_ D2P_Cfg1_SW_Ver_Byte1_21 : 8|8@1+ (1,0) [0|255] ""  PC
 SG_ D2P_Cfg1_SW_Ver_Byte2_21 : 16|8@1+ (1,0) [0|255] ""  PC
 SG_ D2P_Cfg1_SW_Ver_Byte3_21 : 24|8@1+ (1,0) [0|255] ""  PC
 SG_ D2P_Cfg1_SW_Ver_Byte4_21 : 32|8@1+ (1,0) [0|255] ""  PC
 SG_ D2P_Cfg1_SW_Ver_Byte5_21 : 40|8@1+ (1,0) [0|255] ""  PC
 SG_ D2P_Cfg1_SW_Ver_Byte6_21 : 48|8@1+ (1,0) [0|255] ""  PC
 SG_ D2P_Cfg1_SW_Ver_Byte7_21 : 56|8@1+ (1,0) [0|255] ""  PC

BO_ 2499866198 D2P_Cfg1__22: 8 DCDC
 SG_ D2P_Cfg1_SW_Ver_Byte0_22 : 0|8@1+ (1,0) [0|255] ""  PC
 SG_ D2P_Cfg1_SW_Ver_Byte1_22 : 8|8@1+ (1,0) [0|255] ""  PC
 SG_ D2P_Cfg1_SW_Ver_Byte2_22 : 16|8@1+ (1,0) [0|255] ""  PC
 SG_ D2P_Cfg1_SW_Ver_Byte3_22 : 24|8@1+ (1,0) [0|255] ""  PC
 SG_ D2P_Cfg1_SW_Ver_Byte4_22 : 32|8@1+ (1,0) [0|255] ""  PC
 SG_ D2P_Cfg1_SW_Ver_Byte5_22 : 40|8@1+ (1,0) [0|255] ""  PC
 SG_ D2P_Cfg1_SW_Ver_Byte6_22 : 48|8@1+ (1,0) [0|255] ""  PC
 SG_ D2P_Cfg1_SW_Ver_Byte7_22 : 56|8@1+ (1,0) [0|255] ""  PC

BO_ 2499866199 D2P_Cfg1__23: 8 DCDC
 SG_ D2P_Cfg1_SW_Ver_Byte0_23 : 0|8@1+ (1,0) [0|255] ""  PC
 SG_ D2P_Cfg1_SW_Ver_Byte1_23 : 8|8@1+ (1,0) [0|255] ""  PC
 SG_ D2P_Cfg1_SW_Ver_Byte2_23 : 16|8@1+ (1,0) [0|255] ""  PC
 SG_ D2P_Cfg1_SW_Ver_Byte3_23 : 24|8@1+ (1,0) [0|255] ""  PC
 SG_ D2P_Cfg1_SW_Ver_Byte4_23 : 32|8@1+ (1,0) [0|255] ""  PC
 SG_ D2P_Cfg1_SW_Ver_Byte5_23 : 40|8@1+ (1,0) [0|255] ""  PC
 SG_ D2P_Cfg1_SW_Ver_Byte6_23 : 48|8@1+ (1,0) [0|255] ""  PC
 SG_ D2P_Cfg1_SW_Ver_Byte7_23 : 56|8@1+ (1,0) [0|255] ""  PC

BO_ 2499866200 D2P_Cfg1__24: 8 DCDC
 SG_ D2P_Cfg1_SW_Ver_Byte0_24 : 0|8@1+ (1,0) [0|255] ""  PC
 SG_ D2P_Cfg1_SW_Ver_Byte1_24 : 8|8@1+ (1,0) [0|255] ""  PC
 SG_ D2P_Cfg1_SW_Ver_Byte2_24 : 16|8@1+ (1,0) [0|255] ""  PC
 SG_ D2P_Cfg1_SW_Ver_Byte3_24 : 24|8@1+ (1,0) [0|255] ""  PC
 SG_ D2P_Cfg1_SW_Ver_Byte4_24 : 32|8@1+ (1,0) [0|255] ""  PC
 SG_ D2P_Cfg1_SW_Ver_Byte5_24 : 40|8@1+ (1,0) [0|255] ""  PC
 SG_ D2P_Cfg1_SW_Ver_Byte6_24 : 48|8@1+ (1,0) [0|255] ""  PC
 SG_ D2P_Cfg1_SW_Ver_Byte7_24 : 56|8@1+ (1,0) [0|255] ""  PC

BO_ 2499866201 D2P_Cfg1__25: 8 DCDC
 SG_ D2P_Cfg1_SW_Ver_Byte0_25 : 0|8@1+ (1,0) [0|255] ""  PC
 SG_ D2P_Cfg1_SW_Ver_Byte1_25 : 8|8@1+ (1,0) [0|255] ""  PC
 SG_ D2P_Cfg1_SW_Ver_Byte2_25 : 16|8@1+ (1,0) [0|255] ""  PC
 SG_ D2P_Cfg1_SW_Ver_Byte3_25 : 24|8@1+ (1,0) [0|255] ""  PC
 SG_ D2P_Cfg1_SW_Ver_Byte4_25 : 32|8@1+ (1,0) [0|255] ""  PC
 SG_ D2P_Cfg1_SW_Ver_Byte5_25 : 40|8@1+ (1,0) [0|255] ""  PC
 SG_ D2P_Cfg1_SW_Ver_Byte6_25 : 48|8@1+ (1,0) [0|255] ""  PC
 SG_ D2P_Cfg1_SW_Ver_Byte7_25 : 56|8@1+ (1,0) [0|255] ""  PC

BO_ 2499866202 D2P_Cfg1__26: 8 DCDC
 SG_ D2P_Cfg1_SW_Ver_Byte0_26 : 0|8@1+ (1,0) [0|255] ""  PC
 SG_ D2P_Cfg1_SW_Ver_Byte1_26 : 8|8@1+ (1,0) [0|255] ""  PC
 SG_ D2P_Cfg1_SW_Ver_Byte2_26 : 16|8@1+ (1,0) [0|255] ""  PC
 SG_ D2P_Cfg1_SW_Ver_Byte3_26 : 24|8@1+ (1,0) [0|255] ""  PC
 SG_ D2P_Cfg1_SW_Ver_Byte4_26 : 32|8@1+ (1,0) [0|255] ""  PC
 SG_ D2P_Cfg1_SW_Ver_Byte5_26 : 40|8@1+ (1,0) [0|255] ""  PC
 SG_ D2P_Cfg1_SW_Ver_Byte6_26 : 48|8@1+ (1,0) [0|255] ""  PC
 SG_ D2P_Cfg1_SW_Ver_Byte7_26 : 56|8@1+ (1,0) [0|255] ""  PC

BO_ 2499866203 D2P_Cfg1__27: 8 DCDC
 SG_ D2P_Cfg1_SW_Ver_Byte0_27 : 0|8@1+ (1,0) [0|255] ""  PC
 SG_ D2P_Cfg1_SW_Ver_Byte1_27 : 8|8@1+ (1,0) [0|255] ""  PC
 SG_ D2P_Cfg1_SW_Ver_Byte2_27 : 16|8@1+ (1,0) [0|255] ""  PC
 SG_ D2P_Cfg1_SW_Ver_Byte3_27 : 24|8@1+ (1,0) [0|255] ""  PC
 SG_ D2P_Cfg1_SW_Ver_Byte4_27 : 32|8@1+ (1,0) [0|255] ""  PC
 SG_ D2P_Cfg1_SW_Ver_Byte5_27 : 40|8@1+ (1,0) [0|255] ""  PC
 SG_ D2P_Cfg1_SW_Ver_Byte6_27 : 48|8@1+ (1,0) [0|255] ""  PC
 SG_ D2P_Cfg1_SW_Ver_Byte7_27 : 56|8@1+ (1,0) [0|255] ""  PC

BO_ 2499866204 D2P_Cfg1__28: 8 DCDC
 SG_ D2P_Cfg1_SW_Ver_Byte0_28 : 0|8@1+ (1,0) [0|255] ""  PC
 SG_ D2P_Cfg1_SW_Ver_Byte1_28 : 8|8@1+ (1,0) [0|255] ""  PC
 SG_ D2P_Cfg1_SW_Ver_Byte2_28 : 16|8@1+ (1,0) [0|255] ""  PC
 SG_ D2P_Cfg1_SW_Ver_Byte3_28 : 24|8@1+ (1,0) [0|255] ""  PC
 SG_ D2P_Cfg1_SW_Ver_Byte4_28 : 32|8@1+ (1,0) [0|255] ""  PC
 SG_ D2P_Cfg1_SW_Ver_Byte5_28 : 40|8@1+ (1,0) [0|255] ""  PC
 SG_ D2P_Cfg1_SW_Ver_Byte6_28 : 48|8@1+ (1,0) [0|255] ""  PC
 SG_ D2P_Cfg1_SW_Ver_Byte7_28 : 56|8@1+ (1,0) [0|255] ""  PC

BO_ 2499866205 D2P_Cfg1__29: 8 DCDC
 SG_ D2P_Cfg1_SW_Ver_Byte0_29 : 0|8@1+ (1,0) [0|255] ""  PC
 SG_ D2P_Cfg1_SW_Ver_Byte1_29 : 8|8@1+ (1,0) [0|255] ""  PC
 SG_ D2P_Cfg1_SW_Ver_Byte2_29 : 16|8@1+ (1,0) [0|255] ""  PC
 SG_ D2P_Cfg1_SW_Ver_Byte3_29 : 24|8@1+ (1,0) [0|255] ""  PC
 SG_ D2P_Cfg1_SW_Ver_Byte4_29 : 32|8@1+ (1,0) [0|255] ""  PC
 SG_ D2P_Cfg1_SW_Ver_Byte5_29 : 40|8@1+ (1,0) [0|255] ""  PC
 SG_ D2P_Cfg1_SW_Ver_Byte6_29 : 48|8@1+ (1,0) [0|255] ""  PC
 SG_ D2P_Cfg1_SW_Ver_Byte7_29 : 56|8@1+ (1,0) [0|255] ""  PC

BO_ 2499866206 D2P_Cfg1__30: 8 DCDC
 SG_ D2P_Cfg1_SW_Ver_Byte0_30 : 0|8@1+ (1,0) [0|255] ""  PC
 SG_ D2P_Cfg1_SW_Ver_Byte1_30 : 8|8@1+ (1,0) [0|255] ""  PC
 SG_ D2P_Cfg1_SW_Ver_Byte2_30 : 16|8@1+ (1,0) [0|255] ""  PC
 SG_ D2P_Cfg1_SW_Ver_Byte3_30 : 24|8@1+ (1,0) [0|255] ""  PC
 SG_ D2P_Cfg1_SW_Ver_Byte4_30 : 32|8@1+ (1,0) [0|255] ""  PC
 SG_ D2P_Cfg1_SW_Ver_Byte5_30 : 40|8@1+ (1,0) [0|255] ""  PC
 SG_ D2P_Cfg1_SW_Ver_Byte6_30 : 48|8@1+ (1,0) [0|255] ""  PC
 SG_ D2P_Cfg1_SW_Ver_Byte7_30 : 56|8@1+ (1,0) [0|255] ""  PC

BO_ 2499866207 D2P_Cfg1__31: 8 DCDC
 SG_ D2P_Cfg1_SW_Ver_Byte0_31 : 0|8@1+ (1,0) [0|255] ""  PC
 SG_ D2P_Cfg1_SW_Ver_Byte1_31 : 8|8@1+ (1,0) [0|255] ""  PC
 SG_ D2P_Cfg1_SW_Ver_Byte2_31 : 16|8@1+ (1,0) [0|255] ""  PC
 SG_ D2P_Cfg1_SW_Ver_Byte3_31 : 24|8@1+ (1,0) [0|255] ""  PC
 SG_ D2P_Cfg1_SW_Ver_Byte4_31 : 32|8@1+ (1,0) [0|255] ""  PC
 SG_ D2P_Cfg1_SW_Ver_Byte5_31 : 40|8@1+ (1,0) [0|255] ""  PC
 SG_ D2P_Cfg1_SW_Ver_Byte6_31 : 48|8@1+ (1,0) [0|255] ""  PC
 SG_ D2P_Cfg1_SW_Ver_Byte7_31 : 56|8@1+ (1,0) [0|255] ""  PC

BO_ 2499866208 D2P_Cfg1__32: 8 DCDC
 SG_ D2P_Cfg1_SW_Ver_Byte0_32 : 0|8@1+ (1,0) [0|255] ""  PC
 SG_ D2P_Cfg1_SW_Ver_Byte1_32 : 8|8@1+ (1,0) [0|255] ""  PC
 SG_ D2P_Cfg1_SW_Ver_Byte2_32 : 16|8@1+ (1,0) [0|255] ""  PC
 SG_ D2P_Cfg1_SW_Ver_Byte3_32 : 24|8@1+ (1,0) [0|255] ""  PC
 SG_ D2P_Cfg1_SW_Ver_Byte4_32 : 32|8@1+ (1,0) [0|255] ""  PC
 SG_ D2P_Cfg1_SW_Ver_Byte5_32 : 40|8@1+ (1,0) [0|255] ""  PC
 SG_ D2P_Cfg1_SW_Ver_Byte6_32 : 48|8@1+ (1,0) [0|255] ""  PC
 SG_ D2P_Cfg1_SW_Ver_Byte7_32 : 56|8@1+ (1,0) [0|255] ""  PC

BO_ 2499866209 D2P_Cfg1__33: 8 DCDC
 SG_ D2P_Cfg1_SW_Ver_Byte0_33 : 0|8@1+ (1,0) [0|255] ""  PC
 SG_ D2P_Cfg1_SW_Ver_Byte1_33 : 8|8@1+ (1,0) [0|255] ""  PC
 SG_ D2P_Cfg1_SW_Ver_Byte2_33 : 16|8@1+ (1,0) [0|255] ""  PC
 SG_ D2P_Cfg1_SW_Ver_Byte3_33 : 24|8@1+ (1,0) [0|255] ""  PC
 SG_ D2P_Cfg1_SW_Ver_Byte4_33 : 32|8@1+ (1,0) [0|255] ""  PC
 SG_ D2P_Cfg1_SW_Ver_Byte5_33 : 40|8@1+ (1,0) [0|255] ""  PC
 SG_ D2P_Cfg1_SW_Ver_Byte6_33 : 48|8@1+ (1,0) [0|255] ""  PC
 SG_ D2P_Cfg1_SW_Ver_Byte7_33 : 56|8@1+ (1,0) [0|255] ""  PC

BO_ 2499866210 D2P_Cfg1__34: 8 DCDC
 SG_ D2P_Cfg1_SW_Ver_Byte0_34 : 0|8@1+ (1,0) [0|255] ""  PC
 SG_ D2P_Cfg1_SW_Ver_Byte1_34 : 8|8@1+ (1,0) [0|255] ""  PC
 SG_ D2P_Cfg1_SW_Ver_Byte2_34 : 16|8@1+ (1,0) [0|255] ""  PC
 SG_ D2P_Cfg1_SW_Ver_Byte3_34 : 24|8@1+ (1,0) [0|255] ""  PC
 SG_ D2P_Cfg1_SW_Ver_Byte4_34 : 32|8@1+ (1,0) [0|255] ""  PC
 SG_ D2P_Cfg1_SW_Ver_Byte5_34 : 40|8@1+ (1,0) [0|255] ""  PC
 SG_ D2P_Cfg1_SW_Ver_Byte6_34 : 48|8@1+ (1,0) [0|255] ""  PC
 SG_ D2P_Cfg1_SW_Ver_Byte7_34 : 56|8@1+ (1,0) [0|255] ""  PC

BO_ 2499866211 D2P_Cfg1__35: 8 DCDC
 SG_ D2P_Cfg1_SW_Ver_Byte0_35 : 0|8@1+ (1,0) [0|255] ""  PC
 SG_ D2P_Cfg1_SW_Ver_Byte1_35 : 8|8@1+ (1,0) [0|255] ""  PC
 SG_ D2P_Cfg1_SW_Ver_Byte2_35 : 16|8@1+ (1,0) [0|255] ""  PC
 SG_ D2P_Cfg1_SW_Ver_Byte3_35 : 24|8@1+ (1,0) [0|255] ""  PC
 SG_ D2P_Cfg1_SW_Ver_Byte4_35 : 32|8@1+ (1,0) [0|255] ""  PC
 SG_ D2P_Cfg1_SW_Ver_Byte5_35 : 40|8@1+ (1,0) [0|255] ""  PC
 SG_ D2P_Cfg1_SW_Ver_Byte6_35 : 48|8@1+ (1,0) [0|255] ""  PC
 SG_ D2P_Cfg1_SW_Ver_Byte7_35 : 56|8@1+ (1,0) [0|255] ""  PC

BO_ 2499866212 D2P_Cfg1__36: 8 DCDC
 SG_ D2P_Cfg1_SW_Ver_Byte0_36 : 0|8@1+ (1,0) [0|255] ""  PC
 SG_ D2P_Cfg1_SW_Ver_Byte1_36 : 8|8@1+ (1,0) [0|255] ""  PC
 SG_ D2P_Cfg1_SW_Ver_Byte2_36 : 16|8@1+ (1,0) [0|255] ""  PC
 SG_ D2P_Cfg1_SW_Ver_Byte3_36 : 24|8@1+ (1,0) [0|255] ""  PC
 SG_ D2P_Cfg1_SW_Ver_Byte4_36 : 32|8@1+ (1,0) [0|255] ""  PC
 SG_ D2P_Cfg1_SW_Ver_Byte5_36 : 40|8@1+ (1,0) [0|255] ""  PC
 SG_ D2P_Cfg1_SW_Ver_Byte6_36 : 48|8@1+ (1,0) [0|255] ""  PC
 SG_ D2P_Cfg1_SW_Ver_Byte7_36 : 56|8@1+ (1,0) [0|255] ""  PC

BO_ 2499866213 D2P_Cfg1__37: 8 DCDC
 SG_ D2P_Cfg1_SW_Ver_Byte0_37 : 0|8@1+ (1,0) [0|255] ""  PC
 SG_ D2P_Cfg1_SW_Ver_Byte1_37 : 8|8@1+ (1,0) [0|255] ""  PC
 SG_ D2P_Cfg1_SW_Ver_Byte2_37 : 16|8@1+ (1,0) [0|255] ""  PC
 SG_ D2P_Cfg1_SW_Ver_Byte3_37 : 24|8@1+ (1,0) [0|255] ""  PC
 SG_ D2P_Cfg1_SW_Ver_Byte4_37 : 32|8@1+ (1,0) [0|255] ""  PC
 SG_ D2P_Cfg1_SW_Ver_Byte5_37 : 40|8@1+ (1,0) [0|255] ""  PC
 SG_ D2P_Cfg1_SW_Ver_Byte6_37 : 48|8@1+ (1,0) [0|255] ""  PC
 SG_ D2P_Cfg1_SW_Ver_Byte7_37 : 56|8@1+ (1,0) [0|255] ""  PC

BO_ 2499866214 D2P_Cfg1__38: 8 DCDC
 SG_ D2P_Cfg1_SW_Ver_Byte0_38 : 0|8@1+ (1,0) [0|255] ""  PC
 SG_ D2P_Cfg1_SW_Ver_Byte1_38 : 8|8@1+ (1,0) [0|255] ""  PC
 SG_ D2P_Cfg1_SW_Ver_Byte2_38 : 16|8@1+ (1,0) [0|255] ""  PC
 SG_ D2P_Cfg1_SW_Ver_Byte3_38 : 24|8@1+ (1,0) [0|255] ""  PC
 SG_ D2P_Cfg1_SW_Ver_Byte4_38 : 32|8@1+ (1,0) [0|255] ""  PC
 SG_ D2P_Cfg1_SW_Ver_Byte5_38 : 40|8@1+ (1,0) [0|255] ""  PC
 SG_ D2P_Cfg1_SW_Ver_Byte6_38 : 48|8@1+ (1,0) [0|255] ""  PC
 SG_ D2P_Cfg1_SW_Ver_Byte7_38 : 56|8@1+ (1,0) [0|255] ""  PC

BO_ 2499866215 D2P_Cfg1__39: 8 DCDC
 SG_ D2P_Cfg1_SW_Ver_Byte0_39 : 0|8@1+ (1,0) [0|255] ""  PC
 SG_ D2P_Cfg1_SW_Ver_Byte1_39 : 8|8@1+ (1,0) [0|255] ""  PC
 SG_ D2P_Cfg1_SW_Ver_Byte2_39 : 16|8@1+ (1,0) [0|255] ""  PC
 SG_ D2P_Cfg1_SW_Ver_Byte3_39 : 24|8@1+ (1,0) [0|255] ""  PC
 SG_ D2P_Cfg1_SW_Ver_Byte4_39 : 32|8@1+ (1,0) [0|255] ""  PC
 SG_ D2P_Cfg1_SW_Ver_Byte5_39 : 40|8@1+ (1,0) [0|255] ""  PC
 SG_ D2P_Cfg1_SW_Ver_Byte6_39 : 48|8@1+ (1,0) [0|255] ""  PC
 SG_ D2P_Cfg1_SW_Ver_Byte7_39 : 56|8@1+ (1,0) [0|255] ""  PC

BO_ 2499866216 D2P_Cfg1__40: 8 DCDC
 SG_ D2P_Cfg1_SW_Ver_Byte0_40 : 0|8@1+ (1,0) [0|255] ""  PC
 SG_ D2P_Cfg1_SW_Ver_Byte1_40 : 8|8@1+ (1,0) [0|255] ""  PC
 SG_ D2P_Cfg1_SW_Ver_Byte2_40 : 16|8@1+ (1,0) [0|255] ""  PC
 SG_ D2P_Cfg1_SW_Ver_Byte3_40 : 24|8@1+ (1,0) [0|255] ""  PC
 SG_ D2P_Cfg1_SW_Ver_Byte4_40 : 32|8@1+ (1,0) [0|255] ""  PC
 SG_ D2P_Cfg1_SW_Ver_Byte5_40 : 40|8@1+ (1,0) [0|255] ""  PC
 SG_ D2P_Cfg1_SW_Ver_Byte6_40 : 48|8@1+ (1,0) [0|255] ""  PC
 SG_ D2P_Cfg1_SW_Ver_Byte7_40 : 56|8@1+ (1,0) [0|255] ""  PC

BO_ 2499866217 D2P_Cfg1__41: 8 DCDC
 SG_ D2P_Cfg1_SW_Ver_Byte0_41 : 0|8@1+ (1,0) [0|255] ""  PC
 SG_ D2P_Cfg1_SW_Ver_Byte1_41 : 8|8@1+ (1,0) [0|255] ""  PC
 SG_ D2P_Cfg1_SW_Ver_Byte2_41 : 16|8@1+ (1,0) [0|255] ""  PC
 SG_ D2P_Cfg1_SW_Ver_Byte3_41 : 24|8@1+ (1,0) [0|255] ""  PC
 SG_ D2P_Cfg1_SW_Ver_Byte4_41 : 32|8@1+ (1,0) [0|255] ""  PC
 SG_ D2P_Cfg1_SW_Ver_Byte5_41 : 40|8@1+ (1,0) [0|255] ""  PC
 SG_ D2P_Cfg1_SW_Ver_Byte6_41 : 48|8@1+ (1,0) [0|255] ""  PC
 SG_ D2P_Cfg1_SW_Ver_Byte7_41 : 56|8@1+ (1,0) [0|255] ""  PC

BO_ 2499866218 D2P_Cfg1__42: 8 DCDC
 SG_ D2P_Cfg1_SW_Ver_Byte0_42 : 0|8@1+ (1,0) [0|255] ""  PC
 SG_ D2P_Cfg1_SW_Ver_Byte1_42 : 8|8@1+ (1,0) [0|255] ""  PC
 SG_ D2P_Cfg1_SW_Ver_Byte2_42 : 16|8@1+ (1,0) [0|255] ""  PC
 SG_ D2P_Cfg1_SW_Ver_Byte3_42 : 24|8@1+ (1,0) [0|255] ""  PC
 SG_ D2P_Cfg1_SW_Ver_Byte4_42 : 32|8@1+ (1,0) [0|255] ""  PC
 SG_ D2P_Cfg1_SW_Ver_Byte5_42 : 40|8@1+ (1,0) [0|255] ""  PC
 SG_ D2P_Cfg1_SW_Ver_Byte6_42 : 48|8@1+ (1,0) [0|255] ""  PC
 SG_ D2P_Cfg1_SW_Ver_Byte7_42 : 56|8@1+ (1,0) [0|255] ""  PC

BO_ 2499866219 D2P_Cfg1__43: 8 DCDC
 SG_ D2P_Cfg1_SW_Ver_Byte0_43 : 0|8@1+ (1,0) [0|255] ""  PC
 SG_ D2P_Cfg1_SW_Ver_Byte1_43 : 8|8@1+ (1,0) [0|255] ""  PC
 SG_ D2P_Cfg1_SW_Ver_Byte2_43 : 16|8@1+ (1,0) [0|255] ""  PC
 SG_ D2P_Cfg1_SW_Ver_Byte3_43 : 24|8@1+ (1,0) [0|255] ""  PC
 SG_ D2P_Cfg1_SW_Ver_Byte4_43 : 32|8@1+ (1,0) [0|255] ""  PC
 SG_ D2P_Cfg1_SW_Ver_Byte5_43 : 40|8@1+ (1,0) [0|255] ""  PC
 SG_ D2P_Cfg1_SW_Ver_Byte6_43 : 48|8@1+ (1,0) [0|255] ""  PC
 SG_ D2P_Cfg1_SW_Ver_Byte7_43 : 56|8@1+ (1,0) [0|255] ""  PC

BO_ 2499866220 D2P_Cfg1__44: 8 DCDC
 SG_ D2P_Cfg1_SW_Ver_Byte0_44 : 0|8@1+ (1,0) [0|255] ""  PC
 SG_ D2P_Cfg1_SW_Ver_Byte1_44 : 8|8@1+ (1,0) [0|255] ""  PC
 SG_ D2P_Cfg1_SW_Ver_Byte2_44 : 16|8@1+ (1,0) [0|255] ""  PC
 SG_ D2P_Cfg1_SW_Ver_Byte3_44 : 24|8@1+ (1,0) [0|255] ""  PC
 SG_ D2P_Cfg1_SW_Ver_Byte4_44 : 32|8@1+ (1,0) [0|255] ""  PC
 SG_ D2P_Cfg1_SW_Ver_Byte5_44 : 40|8@1+ (1,0) [0|255] ""  PC
 SG_ D2P_Cfg1_SW_Ver_Byte6_44 : 48|8@1+ (1,0) [0|255] ""  PC
 SG_ D2P_Cfg1_SW_Ver_Byte7_44 : 56|8@1+ (1,0) [0|255] ""  PC

BO_ 2499866221 D2P_Cfg1__45: 8 DCDC
 SG_ D2P_Cfg1_SW_Ver_Byte0_45 : 0|8@1+ (1,0) [0|255] ""  PC
 SG_ D2P_Cfg1_SW_Ver_Byte1_45 : 8|8@1+ (1,0) [0|255] ""  PC
 SG_ D2P_Cfg1_SW_Ver_Byte2_45 : 16|8@1+ (1,0) [0|255] ""  PC
 SG_ D2P_Cfg1_SW_Ver_Byte3_45 : 24|8@1+ (1,0) [0|255] ""  PC
 SG_ D2P_Cfg1_SW_Ver_Byte4_45 : 32|8@1+ (1,0) [0|255] ""  PC
 SG_ D2P_Cfg1_SW_Ver_Byte5_45 : 40|8@1+ (1,0) [0|255] ""  PC
 SG_ D2P_Cfg1_SW_Ver_Byte6_45 : 48|8@1+ (1,0) [0|255] ""  PC
 SG_ D2P_Cfg1_SW_Ver_Byte7_45 : 56|8@1+ (1,0) [0|255] ""  PC

BO_ 2499866222 D2P_Cfg1__46: 8 DCDC
 SG_ D2P_Cfg1_SW_Ver_Byte0_46 : 0|8@1+ (1,0) [0|255] ""  PC
 SG_ D2P_Cfg1_SW_Ver_Byte1_46 : 8|8@1+ (1,0) [0|255] ""  PC
 SG_ D2P_Cfg1_SW_Ver_Byte2_46 : 16|8@1+ (1,0) [0|255] ""  PC
 SG_ D2P_Cfg1_SW_Ver_Byte3_46 : 24|8@1+ (1,0) [0|255] ""  PC
 SG_ D2P_Cfg1_SW_Ver_Byte4_46 : 32|8@1+ (1,0) [0|255] ""  PC
 SG_ D2P_Cfg1_SW_Ver_Byte5_46 : 40|8@1+ (1,0) [0|255] ""  PC
 SG_ D2P_Cfg1_SW_Ver_Byte6_46 : 48|8@1+ (1,0) [0|255] ""  PC
 SG_ D2P_Cfg1_SW_Ver_Byte7_46 : 56|8@1+ (1,0) [0|255] ""  PC

BO_ 2499866223 D2P_Cfg1__47: 8 DCDC
 SG_ D2P_Cfg1_SW_Ver_Byte0_47 : 0|8@1+ (1,0) [0|255] ""  PC
 SG_ D2P_Cfg1_SW_Ver_Byte1_47 : 8|8@1+ (1,0) [0|255] ""  PC
 SG_ D2P_Cfg1_SW_Ver_Byte2_47 : 16|8@1+ (1,0) [0|255] ""  PC
 SG_ D2P_Cfg1_SW_Ver_Byte3_47 : 24|8@1+ (1,0) [0|255] ""  PC
 SG_ D2P_Cfg1_SW_Ver_Byte4_47 : 32|8@1+ (1,0) [0|255] ""  PC
 SG_ D2P_Cfg1_SW_Ver_Byte5_47 : 40|8@1+ (1,0) [0|255] ""  PC
 SG_ D2P_Cfg1_SW_Ver_Byte6_47 : 48|8@1+ (1,0) [0|255] ""  PC
 SG_ D2P_Cfg1_SW_Ver_Byte7_47 : 56|8@1+ (1,0) [0|255] ""  PC

BO_ 2499866224 D2P_Cfg1__48: 8 DCDC
 SG_ D2P_Cfg1_SW_Ver_Byte0_48 : 0|8@1+ (1,0) [0|255] ""  PC
 SG_ D2P_Cfg1_SW_Ver_Byte1_48 : 8|8@1+ (1,0) [0|255] ""  PC
 SG_ D2P_Cfg1_SW_Ver_Byte2_48 : 16|8@1+ (1,0) [0|255] ""  PC
 SG_ D2P_Cfg1_SW_Ver_Byte3_48 : 24|8@1+ (1,0) [0|255] ""  PC
 SG_ D2P_Cfg1_SW_Ver_Byte4_48 : 32|8@1+ (1,0) [0|255] ""  PC
 SG_ D2P_Cfg1_SW_Ver_Byte5_48 : 40|8@1+ (1,0) [0|255] ""  PC
 SG_ D2P_Cfg1_SW_Ver_Byte6_48 : 48|8@1+ (1,0) [0|255] ""  PC
 SG_ D2P_Cfg1_SW_Ver_Byte7_48 : 56|8@1+ (1,0) [0|255] ""  PC

BO_ 2499866225 D2P_Cfg1__49: 8 DCDC
 SG_ D2P_Cfg1_SW_Ver_Byte0_49 : 0|8@1+ (1,0) [0|255] ""  PC
 SG_ D2P_Cfg1_SW_Ver_Byte1_49 : 8|8@1+ (1,0) [0|255] ""  PC
 SG_ D2P_Cfg1_SW_Ver_Byte2_49 : 16|8@1+ (1,0) [0|255] ""  PC
 SG_ D2P_Cfg1_SW_Ver_Byte3_49 : 24|8@1+ (1,0) [0|255] ""  PC
 SG_ D2P_Cfg1_SW_Ver_Byte4_49 : 32|8@1+ (1,0) [0|255] ""  PC
 SG_ D2P_Cfg1_SW_Ver_Byte5_49 : 40|8@1+ (1,0) [0|255] ""  PC
 SG_ D2P_Cfg1_SW_Ver_Byte6_49 : 48|8@1+ (1,0) [0|255] ""  PC
 SG_ D2P_Cfg1_SW_Ver_Byte7_49 : 56|8@1+ (1,0) [0|255] ""  PC

BO_ 2499866226 D2P_Cfg1__50: 8 DCDC
 SG_ D2P_Cfg1_SW_Ver_Byte0_50 : 0|8@1+ (1,0) [0|255] ""  PC
 SG_ D2P_Cfg1_SW_Ver_Byte1_50 : 8|8@1+ (1,0) [0|255] ""  PC
 SG_ D2P_Cfg1_SW_Ver_Byte2_50 : 16|8@1+ (1,0) [0|255] ""  PC
 SG_ D2P_Cfg1_SW_Ver_Byte3_50 : 24|8@1+ (1,0) [0|255] ""  PC
 SG_ D2P_Cfg1_SW_Ver_Byte4_50 : 32|8@1+ (1,0) [0|255] ""  PC
 SG_ D2P_Cfg1_SW_Ver_Byte5_50 : 40|8@1+ (1,0) [0|255] ""  PC
 SG_ D2P_Cfg1_SW_Ver_Byte6_50 : 48|8@1+ (1,0) [0|255] ""  PC
 SG_ D2P_Cfg1_SW_Ver_Byte7_50 : 56|8@1+ (1,0) [0|255] ""  PC

BO_ 2499866227 D2P_Cfg1__51: 8 DCDC
 SG_ D2P_Cfg1_SW_Ver_Byte0_51 : 0|8@1+ (1,0) [0|255] ""  PC
 SG_ D2P_Cfg1_SW_Ver_Byte1_51 : 8|8@1+ (1,0) [0|255] ""  PC
 SG_ D2P_Cfg1_SW_Ver_Byte2_51 : 16|8@1+ (1,0) [0|255] ""  PC
 SG_ D2P_Cfg1_SW_Ver_Byte3_51 : 24|8@1+ (1,0) [0|255] ""  PC
 SG_ D2P_Cfg1_SW_Ver_Byte4_51 : 32|8@1+ (1,0) [0|255] ""  PC
 SG_ D2P_Cfg1_SW_Ver_Byte5_51 : 40|8@1+ (1,0) [0|255] ""  PC
 SG_ D2P_Cfg1_SW_Ver_Byte6_51 : 48|8@1+ (1,0) [0|255] ""  PC
 SG_ D2P_Cfg1_SW_Ver_Byte7_51 : 56|8@1+ (1,0) [0|255] ""  PC

BO_ 2499866228 D2P_Cfg1__52: 8 DCDC
 SG_ D2P_Cfg1_SW_Ver_Byte0_52 : 0|8@1+ (1,0) [0|255] ""  PC
 SG_ D2P_Cfg1_SW_Ver_Byte1_52 : 8|8@1+ (1,0) [0|255] ""  PC
 SG_ D2P_Cfg1_SW_Ver_Byte2_52 : 16|8@1+ (1,0) [0|255] ""  PC
 SG_ D2P_Cfg1_SW_Ver_Byte3_52 : 24|8@1+ (1,0) [0|255] ""  PC
 SG_ D2P_Cfg1_SW_Ver_Byte4_52 : 32|8@1+ (1,0) [0|255] ""  PC
 SG_ D2P_Cfg1_SW_Ver_Byte5_52 : 40|8@1+ (1,0) [0|255] ""  PC
 SG_ D2P_Cfg1_SW_Ver_Byte6_52 : 48|8@1+ (1,0) [0|255] ""  PC
 SG_ D2P_Cfg1_SW_Ver_Byte7_52 : 56|8@1+ (1,0) [0|255] ""  PC

BO_ 2499866229 D2P_Cfg1__53: 8 DCDC
 SG_ D2P_Cfg1_SW_Ver_Byte0_53 : 0|8@1+ (1,0) [0|255] ""  PC
 SG_ D2P_Cfg1_SW_Ver_Byte1_53 : 8|8@1+ (1,0) [0|255] ""  PC
 SG_ D2P_Cfg1_SW_Ver_Byte2_53 : 16|8@1+ (1,0) [0|255] ""  PC
 SG_ D2P_Cfg1_SW_Ver_Byte3_53 : 24|8@1+ (1,0) [0|255] ""  PC
 SG_ D2P_Cfg1_SW_Ver_Byte4_53 : 32|8@1+ (1,0) [0|255] ""  PC
 SG_ D2P_Cfg1_SW_Ver_Byte5_53 : 40|8@1+ (1,0) [0|255] ""  PC
 SG_ D2P_Cfg1_SW_Ver_Byte6_53 : 48|8@1+ (1,0) [0|255] ""  PC
 SG_ D2P_Cfg1_SW_Ver_Byte7_53 : 56|8@1+ (1,0) [0|255] ""  PC

BO_ 2499866230 D2P_Cfg1__54: 8 DCDC
 SG_ D2P_Cfg1_SW_Ver_Byte0_54 : 0|8@1+ (1,0) [0|255] ""  PC
 SG_ D2P_Cfg1_SW_Ver_Byte1_54 : 8|8@1+ (1,0) [0|255] ""  PC
 SG_ D2P_Cfg1_SW_Ver_Byte2_54 : 16|8@1+ (1,0) [0|255] ""  PC
 SG_ D2P_Cfg1_SW_Ver_Byte3_54 : 24|8@1+ (1,0) [0|255] ""  PC
 SG_ D2P_Cfg1_SW_Ver_Byte4_54 : 32|8@1+ (1,0) [0|255] ""  PC
 SG_ D2P_Cfg1_SW_Ver_Byte5_54 : 40|8@1+ (1,0) [0|255] ""  PC
 SG_ D2P_Cfg1_SW_Ver_Byte6_54 : 48|8@1+ (1,0) [0|255] ""  PC
 SG_ D2P_Cfg1_SW_Ver_Byte7_54 : 56|8@1+ (1,0) [0|255] ""  PC

BO_ 2499866231 D2P_Cfg1__55: 8 DCDC
 SG_ D2P_Cfg1_SW_Ver_Byte0_55 : 0|8@1+ (1,0) [0|255] ""  PC
 SG_ D2P_Cfg1_SW_Ver_Byte1_55 : 8|8@1+ (1,0) [0|255] ""  PC
 SG_ D2P_Cfg1_SW_Ver_Byte2_55 : 16|8@1+ (1,0) [0|255] ""  PC
 SG_ D2P_Cfg1_SW_Ver_Byte3_55 : 24|8@1+ (1,0) [0|255] ""  PC
 SG_ D2P_Cfg1_SW_Ver_Byte4_55 : 32|8@1+ (1,0) [0|255] ""  PC
 SG_ D2P_Cfg1_SW_Ver_Byte5_55 : 40|8@1+ (1,0) [0|255] ""  PC
 SG_ D2P_Cfg1_SW_Ver_Byte6_55 : 48|8@1+ (1,0) [0|255] ""  PC
 SG_ D2P_Cfg1_SW_Ver_Byte7_55 : 56|8@1+ (1,0) [0|255] ""  PC

BO_ 2499866232 D2P_Cfg1__56: 8 DCDC
 SG_ D2P_Cfg1_SW_Ver_Byte0_56 : 0|8@1+ (1,0) [0|255] ""  PC
 SG_ D2P_Cfg1_SW_Ver_Byte1_56 : 8|8@1+ (1,0) [0|255] ""  PC
 SG_ D2P_Cfg1_SW_Ver_Byte2_56 : 16|8@1+ (1,0) [0|255] ""  PC
 SG_ D2P_Cfg1_SW_Ver_Byte3_56 : 24|8@1+ (1,0) [0|255] ""  PC
 SG_ D2P_Cfg1_SW_Ver_Byte4_56 : 32|8@1+ (1,0) [0|255] ""  PC
 SG_ D2P_Cfg1_SW_Ver_Byte5_56 : 40|8@1+ (1,0) [0|255] ""  PC
 SG_ D2P_Cfg1_SW_Ver_Byte6_56 : 48|8@1+ (1,0) [0|255] ""  PC
 SG_ D2P_Cfg1_SW_Ver_Byte7_56 : 56|8@1+ (1,0) [0|255] ""  PC

BO_ 2499866233 D2P_Cfg1__57: 8 DCDC
 SG_ D2P_Cfg1_SW_Ver_Byte0_57 : 0|8@1+ (1,0) [0|255] ""  PC
 SG_ D2P_Cfg1_SW_Ver_Byte1_57 : 8|8@1+ (1,0) [0|255] ""  PC
 SG_ D2P_Cfg1_SW_Ver_Byte2_57 : 16|8@1+ (1,0) [0|255] ""  PC
 SG_ D2P_Cfg1_SW_Ver_Byte3_57 : 24|8@1+ (1,0) [0|255] ""  PC
 SG_ D2P_Cfg1_SW_Ver_Byte4_57 : 32|8@1+ (1,0) [0|255] ""  PC
 SG_ D2P_Cfg1_SW_Ver_Byte5_57 : 40|8@1+ (1,0) [0|255] ""  PC
 SG_ D2P_Cfg1_SW_Ver_Byte6_57 : 48|8@1+ (1,0) [0|255] ""  PC
 SG_ D2P_Cfg1_SW_Ver_Byte7_57 : 56|8@1+ (1,0) [0|255] ""  PC

BO_ 2499866234 D2P_Cfg1__58: 8 DCDC
 SG_ D2P_Cfg1_SW_Ver_Byte0_58 : 0|8@1+ (1,0) [0|255] ""  PC
 SG_ D2P_Cfg1_SW_Ver_Byte1_58 : 8|8@1+ (1,0) [0|255] ""  PC
 SG_ D2P_Cfg1_SW_Ver_Byte2_58 : 16|8@1+ (1,0) [0|255] ""  PC
 SG_ D2P_Cfg1_SW_Ver_Byte3_58 : 24|8@1+ (1,0) [0|255] ""  PC
 SG_ D2P_Cfg1_SW_Ver_Byte4_58 : 32|8@1+ (1,0) [0|255] ""  PC
 SG_ D2P_Cfg1_SW_Ver_Byte5_58 : 40|8@1+ (1,0) [0|255] ""  PC
 SG_ D2P_Cfg1_SW_Ver_Byte6_58 : 48|8@1+ (1,0) [0|255] ""  PC
 SG_ D2P_Cfg1_SW_Ver_Byte7_58 : 56|8@1+ (1,0) [0|255] ""  PC

BO_ 2499866235 D2P_Cfg1__59: 8 DCDC
 SG_ D2P_Cfg1_SW_Ver_Byte0_59 : 0|8@1+ (1,0) [0|255] ""  PC
 SG_ D2P_Cfg1_SW_Ver_Byte1_59 : 8|8@1+ (1,0) [0|255] ""  PC
 SG_ D2P_Cfg1_SW_Ver_Byte2_59 : 16|8@1+ (1,0) [0|255] ""  PC
 SG_ D2P_Cfg1_SW_Ver_Byte3_59 : 24|8@1+ (1,0) [0|255] ""  PC
 SG_ D2P_Cfg1_SW_Ver_Byte4_59 : 32|8@1+ (1,0) [0|255] ""  PC
 SG_ D2P_Cfg1_SW_Ver_Byte5_59 : 40|8@1+ (1,0) [0|255] ""  PC
 SG_ D2P_Cfg1_SW_Ver_Byte6_59 : 48|8@1+ (1,0) [0|255] ""  PC
 SG_ D2P_Cfg1_SW_Ver_Byte7_59 : 56|8@1+ (1,0) [0|255] ""  PC

BO_ 2499866236 D2P_Cfg1__60: 8 DCDC
 SG_ D2P_Cfg1_SW_Ver_Byte0_60 : 0|8@1+ (1,0) [0|255] ""  PC
 SG_ D2P_Cfg1_SW_Ver_Byte1_60 : 8|8@1+ (1,0) [0|255] ""  PC
 SG_ D2P_Cfg1_SW_Ver_Byte2_60 : 16|8@1+ (1,0) [0|255] ""  PC
 SG_ D2P_Cfg1_SW_Ver_Byte3_60 : 24|8@1+ (1,0) [0|255] ""  PC
 SG_ D2P_Cfg1_SW_Ver_Byte4_60 : 32|8@1+ (1,0) [0|255] ""  PC
 SG_ D2P_Cfg1_SW_Ver_Byte5_60 : 40|8@1+ (1,0) [0|255] ""  PC
 SG_ D2P_Cfg1_SW_Ver_Byte6_60 : 48|8@1+ (1,0) [0|255] ""  PC
 SG_ D2P_Cfg1_SW_Ver_Byte7_60 : 56|8@1+ (1,0) [0|255] ""  PC

BO_ 2499866237 D2P_Cfg1__61: 8 DCDC
 SG_ D2P_Cfg1_SW_Ver_Byte0_61 : 0|8@1+ (1,0) [0|255] ""  PC
 SG_ D2P_Cfg1_SW_Ver_Byte1_61 : 8|8@1+ (1,0) [0|255] ""  PC
 SG_ D2P_Cfg1_SW_Ver_Byte2_61 : 16|8@1+ (1,0) [0|255] ""  PC
 SG_ D2P_Cfg1_SW_Ver_Byte3_61 : 24|8@1+ (1,0) [0|255] ""  PC
 SG_ D2P_Cfg1_SW_Ver_Byte4_61 : 32|8@1+ (1,0) [0|255] ""  PC
 SG_ D2P_Cfg1_SW_Ver_Byte5_61 : 40|8@1+ (1,0) [0|255] ""  PC
 SG_ D2P_Cfg1_SW_Ver_Byte6_61 : 48|8@1+ (1,0) [0|255] ""  PC
 SG_ D2P_Cfg1_SW_Ver_Byte7_61 : 56|8@1+ (1,0) [0|255] ""  PC

BO_ 2499866238 D2P_Cfg1__62: 8 DCDC
 SG_ D2P_Cfg1_SW_Ver_Byte0_62 : 0|8@1+ (1,0) [0|255] ""  PC
 SG_ D2P_Cfg1_SW_Ver_Byte1_62 : 8|8@1+ (1,0) [0|255] ""  PC
 SG_ D2P_Cfg1_SW_Ver_Byte2_62 : 16|8@1+ (1,0) [0|255] ""  PC
 SG_ D2P_Cfg1_SW_Ver_Byte3_62 : 24|8@1+ (1,0) [0|255] ""  PC
 SG_ D2P_Cfg1_SW_Ver_Byte4_62 : 32|8@1+ (1,0) [0|255] ""  PC
 SG_ D2P_Cfg1_SW_Ver_Byte5_62 : 40|8@1+ (1,0) [0|255] ""  PC
 SG_ D2P_Cfg1_SW_Ver_Byte6_62 : 48|8@1+ (1,0) [0|255] ""  PC
 SG_ D2P_Cfg1_SW_Ver_Byte7_62 : 56|8@1+ (1,0) [0|255] ""  PC

BO_ 2499866239 D2P_Cfg1__63: 8 DCDC
 SG_ D2P_Cfg1_SW_Ver_Byte0_63 : 0|8@1+ (1,0) [0|255] ""  PC
 SG_ D2P_Cfg1_SW_Ver_Byte1_63 : 8|8@1+ (1,0) [0|255] ""  PC
 SG_ D2P_Cfg1_SW_Ver_Byte2_63 : 16|8@1+ (1,0) [0|255] ""  PC
 SG_ D2P_Cfg1_SW_Ver_Byte3_63 : 24|8@1+ (1,0) [0|255] ""  PC
 SG_ D2P_Cfg1_SW_Ver_Byte4_63 : 32|8@1+ (1,0) [0|255] ""  PC
 SG_ D2P_Cfg1_SW_Ver_Byte5_63 : 40|8@1+ (1,0) [0|255] ""  PC
 SG_ D2P_Cfg1_SW_Ver_Byte6_63 : 48|8@1+ (1,0) [0|255] ""  PC
 SG_ D2P_Cfg1_SW_Ver_Byte7_63 : 56|8@1+ (1,0) [0|255] ""  PC

BO_ 2499931713 D2P_Cfg2__01: 8 DCDC
 SG_ D2P_Cfg2_SW_Ver_Byte8_01 : 0|8@1+ (1,0) [0|255] ""  PC
 SG_ D2P_Cfg2_SW_Ver_Byte9_01 : 8|8@1+ (1,0) [0|255] ""  PC
 SG_ D2P_Cfg2_SW_Ver_Byte10_01 : 16|8@1+ (1,0) [0|255] ""  PC
 SG_ D2P_Cfg2_SW_Ver_Byte11_01 : 24|8@1+ (1,0) [0|255] ""  PC
 SG_ D2P_Cfg2_SW_Ver_Byte12_01 : 32|8@1+ (1,0) [0|255] ""  PC
 SG_ D2P_Cfg2_SW_Ver_Byte13_01 : 40|8@1+ (1,0) [0|255] ""  PC
 SG_ D2P_Cfg2_SW_Ver_Byte14_01 : 48|8@1+ (1,0) [0|255] ""  PC
 SG_ D2P_Cfg2_SW_Ver_Byte15_01 : 56|8@1+ (1,0) [0|255] ""  PC

BO_ 2499931714 D2P_Cfg2__02: 8 DCDC
 SG_ D2P_Cfg2_SW_Ver_Byte8_02 : 0|8@1+ (1,0) [0|255] ""  PC
 SG_ D2P_Cfg2_SW_Ver_Byte9_02 : 8|8@1+ (1,0) [0|255] ""  PC
 SG_ D2P_Cfg2_SW_Ver_Byte10_02 : 16|8@1+ (1,0) [0|255] ""  PC
 SG_ D2P_Cfg2_SW_Ver_Byte11_02 : 24|8@1+ (1,0) [0|255] ""  PC
 SG_ D2P_Cfg2_SW_Ver_Byte12_02 : 32|8@1+ (1,0) [0|255] ""  PC
 SG_ D2P_Cfg2_SW_Ver_Byte13_02 : 40|8@1+ (1,0) [0|255] ""  PC
 SG_ D2P_Cfg2_SW_Ver_Byte14_02 : 48|8@1+ (1,0) [0|255] ""  PC
 SG_ D2P_Cfg2_SW_Ver_Byte15_02 : 56|8@1+ (1,0) [0|255] ""  PC

BO_ 2499931715 D2P_Cfg2__03: 8 DCDC
 SG_ D2P_Cfg2_SW_Ver_Byte8_03 : 0|8@1+ (1,0) [0|255] ""  PC
 SG_ D2P_Cfg2_SW_Ver_Byte9_03 : 8|8@1+ (1,0) [0|255] ""  PC
 SG_ D2P_Cfg2_SW_Ver_Byte10_03 : 16|8@1+ (1,0) [0|255] ""  PC
 SG_ D2P_Cfg2_SW_Ver_Byte11_03 : 24|8@1+ (1,0) [0|255] ""  PC
 SG_ D2P_Cfg2_SW_Ver_Byte12_03 : 32|8@1+ (1,0) [0|255] ""  PC
 SG_ D2P_Cfg2_SW_Ver_Byte13_03 : 40|8@1+ (1,0) [0|255] ""  PC
 SG_ D2P_Cfg2_SW_Ver_Byte14_03 : 48|8@1+ (1,0) [0|255] ""  PC
 SG_ D2P_Cfg2_SW_Ver_Byte15_03 : 56|8@1+ (1,0) [0|255] ""  PC

BO_ 2499931716 D2P_Cfg2__04: 8 DCDC
 SG_ D2P_Cfg2_SW_Ver_Byte8_04 : 0|8@1+ (1,0) [0|255] ""  PC
 SG_ D2P_Cfg2_SW_Ver_Byte9_04 : 8|8@1+ (1,0) [0|255] ""  PC
 SG_ D2P_Cfg2_SW_Ver_Byte10_04 : 16|8@1+ (1,0) [0|255] ""  PC
 SG_ D2P_Cfg2_SW_Ver_Byte11_04 : 24|8@1+ (1,0) [0|255] ""  PC
 SG_ D2P_Cfg2_SW_Ver_Byte12_04 : 32|8@1+ (1,0) [0|255] ""  PC
 SG_ D2P_Cfg2_SW_Ver_Byte13_04 : 40|8@1+ (1,0) [0|255] ""  PC
 SG_ D2P_Cfg2_SW_Ver_Byte14_04 : 48|8@1+ (1,0) [0|255] ""  PC
 SG_ D2P_Cfg2_SW_Ver_Byte15_04 : 56|8@1+ (1,0) [0|255] ""  PC

BO_ 2499931717 D2P_Cfg2__05: 8 DCDC
 SG_ D2P_Cfg2_SW_Ver_Byte8_05 : 0|8@1+ (1,0) [0|255] ""  PC
 SG_ D2P_Cfg2_SW_Ver_Byte9_05 : 8|8@1+ (1,0) [0|255] ""  PC
 SG_ D2P_Cfg2_SW_Ver_Byte10_05 : 16|8@1+ (1,0) [0|255] ""  PC
 SG_ D2P_Cfg2_SW_Ver_Byte11_05 : 24|8@1+ (1,0) [0|255] ""  PC
 SG_ D2P_Cfg2_SW_Ver_Byte12_05 : 32|8@1+ (1,0) [0|255] ""  PC
 SG_ D2P_Cfg2_SW_Ver_Byte13_05 : 40|8@1+ (1,0) [0|255] ""  PC
 SG_ D2P_Cfg2_SW_Ver_Byte14_05 : 48|8@1+ (1,0) [0|255] ""  PC
 SG_ D2P_Cfg2_SW_Ver_Byte15_05 : 56|8@1+ (1,0) [0|255] ""  PC

BO_ 2499931718 D2P_Cfg2__06: 8 DCDC
 SG_ D2P_Cfg2_SW_Ver_Byte8_06 : 0|8@1+ (1,0) [0|255] ""  PC
 SG_ D2P_Cfg2_SW_Ver_Byte9_06 : 8|8@1+ (1,0) [0|255] ""  PC
 SG_ D2P_Cfg2_SW_Ver_Byte10_06 : 16|8@1+ (1,0) [0|255] ""  PC
 SG_ D2P_Cfg2_SW_Ver_Byte11_06 : 24|8@1+ (1,0) [0|255] ""  PC
 SG_ D2P_Cfg2_SW_Ver_Byte12_06 : 32|8@1+ (1,0) [0|255] ""  PC
 SG_ D2P_Cfg2_SW_Ver_Byte13_06 : 40|8@1+ (1,0) [0|255] ""  PC
 SG_ D2P_Cfg2_SW_Ver_Byte14_06 : 48|8@1+ (1,0) [0|255] ""  PC
 SG_ D2P_Cfg2_SW_Ver_Byte15_06 : 56|8@1+ (1,0) [0|255] ""  PC

BO_ 2499931719 D2P_Cfg2__07: 8 DCDC
 SG_ D2P_Cfg2_SW_Ver_Byte8_07 : 0|8@1+ (1,0) [0|255] ""  PC
 SG_ D2P_Cfg2_SW_Ver_Byte9_07 : 8|8@1+ (1,0) [0|255] ""  PC
 SG_ D2P_Cfg2_SW_Ver_Byte10_07 : 16|8@1+ (1,0) [0|255] ""  PC
 SG_ D2P_Cfg2_SW_Ver_Byte11_07 : 24|8@1+ (1,0) [0|255] ""  PC
 SG_ D2P_Cfg2_SW_Ver_Byte12_07 : 32|8@1+ (1,0) [0|255] ""  PC
 SG_ D2P_Cfg2_SW_Ver_Byte13_07 : 40|8@1+ (1,0) [0|255] ""  PC
 SG_ D2P_Cfg2_SW_Ver_Byte14_07 : 48|8@1+ (1,0) [0|255] ""  PC
 SG_ D2P_Cfg2_SW_Ver_Byte15_07 : 56|8@1+ (1,0) [0|255] ""  PC

BO_ 2499931720 D2P_Cfg2__08: 8 DCDC
 SG_ D2P_Cfg2_SW_Ver_Byte8_08 : 0|8@1+ (1,0) [0|255] ""  PC
 SG_ D2P_Cfg2_SW_Ver_Byte9_08 : 8|8@1+ (1,0) [0|255] ""  PC
 SG_ D2P_Cfg2_SW_Ver_Byte10_08 : 16|8@1+ (1,0) [0|255] ""  PC
 SG_ D2P_Cfg2_SW_Ver_Byte11_08 : 24|8@1+ (1,0) [0|255] ""  PC
 SG_ D2P_Cfg2_SW_Ver_Byte12_08 : 32|8@1+ (1,0) [0|255] ""  PC
 SG_ D2P_Cfg2_SW_Ver_Byte13_08 : 40|8@1+ (1,0) [0|255] ""  PC
 SG_ D2P_Cfg2_SW_Ver_Byte14_08 : 48|8@1+ (1,0) [0|255] ""  PC
 SG_ D2P_Cfg2_SW_Ver_Byte15_08 : 56|8@1+ (1,0) [0|255] ""  PC

BO_ 2499931721 D2P_Cfg2__09: 8 DCDC
 SG_ D2P_Cfg2_SW_Ver_Byte8_09 : 0|8@1+ (1,0) [0|255] ""  PC
 SG_ D2P_Cfg2_SW_Ver_Byte9_09 : 8|8@1+ (1,0) [0|255] ""  PC
 SG_ D2P_Cfg2_SW_Ver_Byte10_09 : 16|8@1+ (1,0) [0|255] ""  PC
 SG_ D2P_Cfg2_SW_Ver_Byte11_09 : 24|8@1+ (1,0) [0|255] ""  PC
 SG_ D2P_Cfg2_SW_Ver_Byte12_09 : 32|8@1+ (1,0) [0|255] ""  PC
 SG_ D2P_Cfg2_SW_Ver_Byte13_09 : 40|8@1+ (1,0) [0|255] ""  PC
 SG_ D2P_Cfg2_SW_Ver_Byte14_09 : 48|8@1+ (1,0) [0|255] ""  PC
 SG_ D2P_Cfg2_SW_Ver_Byte15_09 : 56|8@1+ (1,0) [0|255] ""  PC

BO_ 2499931722 D2P_Cfg2__10: 8 DCDC
 SG_ D2P_Cfg2_SW_Ver_Byte8_10 : 0|8@1+ (1,0) [0|255] ""  PC
 SG_ D2P_Cfg2_SW_Ver_Byte9_10 : 8|8@1+ (1,0) [0|255] ""  PC
 SG_ D2P_Cfg2_SW_Ver_Byte10_10 : 16|8@1+ (1,0) [0|255] ""  PC
 SG_ D2P_Cfg2_SW_Ver_Byte11_10 : 24|8@1+ (1,0) [0|255] ""  PC
 SG_ D2P_Cfg2_SW_Ver_Byte12_10 : 32|8@1+ (1,0) [0|255] ""  PC
 SG_ D2P_Cfg2_SW_Ver_Byte13_10 : 40|8@1+ (1,0) [0|255] ""  PC
 SG_ D2P_Cfg2_SW_Ver_Byte14_10 : 48|8@1+ (1,0) [0|255] ""  PC
 SG_ D2P_Cfg2_SW_Ver_Byte15_10 : 56|8@1+ (1,0) [0|255] ""  PC

BO_ 2499931723 D2P_Cfg2__11: 8 DCDC
 SG_ D2P_Cfg2_SW_Ver_Byte8_11 : 0|8@1+ (1,0) [0|255] ""  PC
 SG_ D2P_Cfg2_SW_Ver_Byte9_11 : 8|8@1+ (1,0) [0|255] ""  PC
 SG_ D2P_Cfg2_SW_Ver_Byte10_11 : 16|8@1+ (1,0) [0|255] ""  PC
 SG_ D2P_Cfg2_SW_Ver_Byte11_11 : 24|8@1+ (1,0) [0|255] ""  PC
 SG_ D2P_Cfg2_SW_Ver_Byte12_11 : 32|8@1+ (1,0) [0|255] ""  PC
 SG_ D2P_Cfg2_SW_Ver_Byte13_11 : 40|8@1+ (1,0) [0|255] ""  PC
 SG_ D2P_Cfg2_SW_Ver_Byte14_11 : 48|8@1+ (1,0) [0|255] ""  PC
 SG_ D2P_Cfg2_SW_Ver_Byte15_11 : 56|8@1+ (1,0) [0|255] ""  PC

BO_ 2499931724 D2P_Cfg2__12: 8 DCDC
 SG_ D2P_Cfg2_SW_Ver_Byte8_12 : 0|8@1+ (1,0) [0|255] ""  PC
 SG_ D2P_Cfg2_SW_Ver_Byte9_12 : 8|8@1+ (1,0) [0|255] ""  PC
 SG_ D2P_Cfg2_SW_Ver_Byte10_12 : 16|8@1+ (1,0) [0|255] ""  PC
 SG_ D2P_Cfg2_SW_Ver_Byte11_12 : 24|8@1+ (1,0) [0|255] ""  PC
 SG_ D2P_Cfg2_SW_Ver_Byte12_12 : 32|8@1+ (1,0) [0|255] ""  PC
 SG_ D2P_Cfg2_SW_Ver_Byte13_12 : 40|8@1+ (1,0) [0|255] ""  PC
 SG_ D2P_Cfg2_SW_Ver_Byte14_12 : 48|8@1+ (1,0) [0|255] ""  PC
 SG_ D2P_Cfg2_SW_Ver_Byte15_12 : 56|8@1+ (1,0) [0|255] ""  PC

BO_ 2499931725 D2P_Cfg2__13: 8 DCDC
 SG_ D2P_Cfg2_SW_Ver_Byte8_13 : 0|8@1+ (1,0) [0|255] ""  PC
 SG_ D2P_Cfg2_SW_Ver_Byte9_13 : 8|8@1+ (1,0) [0|255] ""  PC
 SG_ D2P_Cfg2_SW_Ver_Byte10_13 : 16|8@1+ (1,0) [0|255] ""  PC
 SG_ D2P_Cfg2_SW_Ver_Byte11_13 : 24|8@1+ (1,0) [0|255] ""  PC
 SG_ D2P_Cfg2_SW_Ver_Byte12_13 : 32|8@1+ (1,0) [0|255] ""  PC
 SG_ D2P_Cfg2_SW_Ver_Byte13_13 : 40|8@1+ (1,0) [0|255] ""  PC
 SG_ D2P_Cfg2_SW_Ver_Byte14_13 : 48|8@1+ (1,0) [0|255] ""  PC
 SG_ D2P_Cfg2_SW_Ver_Byte15_13 : 56|8@1+ (1,0) [0|255] ""  PC

BO_ 2499931726 D2P_Cfg2__14: 8 DCDC
 SG_ D2P_Cfg2_SW_Ver_Byte8_14 : 0|8@1+ (1,0) [0|255] ""  PC
 SG_ D2P_Cfg2_SW_Ver_Byte9_14 : 8|8@1+ (1,0) [0|255] ""  PC
 SG_ D2P_Cfg2_SW_Ver_Byte10_14 : 16|8@1+ (1,0) [0|255] ""  PC
 SG_ D2P_Cfg2_SW_Ver_Byte11_14 : 24|8@1+ (1,0) [0|255] ""  PC
 SG_ D2P_Cfg2_SW_Ver_Byte12_14 : 32|8@1+ (1,0) [0|255] ""  PC
 SG_ D2P_Cfg2_SW_Ver_Byte13_14 : 40|8@1+ (1,0) [0|255] ""  PC
 SG_ D2P_Cfg2_SW_Ver_Byte14_14 : 48|8@1+ (1,0) [0|255] ""  PC
 SG_ D2P_Cfg2_SW_Ver_Byte15_14 : 56|8@1+ (1,0) [0|255] ""  PC

BO_ 2499931727 D2P_Cfg2__15: 8 DCDC
 SG_ D2P_Cfg2_SW_Ver_Byte8_15 : 0|8@1+ (1,0) [0|255] ""  PC
 SG_ D2P_Cfg2_SW_Ver_Byte9_15 : 8|8@1+ (1,0) [0|255] ""  PC
 SG_ D2P_Cfg2_SW_Ver_Byte10_15 : 16|8@1+ (1,0) [0|255] ""  PC
 SG_ D2P_Cfg2_SW_Ver_Byte11_15 : 24|8@1+ (1,0) [0|255] ""  PC
 SG_ D2P_Cfg2_SW_Ver_Byte12_15 : 32|8@1+ (1,0) [0|255] ""  PC
 SG_ D2P_Cfg2_SW_Ver_Byte13_15 : 40|8@1+ (1,0) [0|255] ""  PC
 SG_ D2P_Cfg2_SW_Ver_Byte14_15 : 48|8@1+ (1,0) [0|255] ""  PC
 SG_ D2P_Cfg2_SW_Ver_Byte15_15 : 56|8@1+ (1,0) [0|255] ""  PC

BO_ 2499931728 D2P_Cfg2__16: 8 DCDC
 SG_ D2P_Cfg2_SW_Ver_Byte8_16 : 0|8@1+ (1,0) [0|255] ""  PC
 SG_ D2P_Cfg2_SW_Ver_Byte9_16 : 8|8@1+ (1,0) [0|255] ""  PC
 SG_ D2P_Cfg2_SW_Ver_Byte10_16 : 16|8@1+ (1,0) [0|255] ""  PC
 SG_ D2P_Cfg2_SW_Ver_Byte11_16 : 24|8@1+ (1,0) [0|255] ""  PC
 SG_ D2P_Cfg2_SW_Ver_Byte12_16 : 32|8@1+ (1,0) [0|255] ""  PC
 SG_ D2P_Cfg2_SW_Ver_Byte13_16 : 40|8@1+ (1,0) [0|255] ""  PC
 SG_ D2P_Cfg2_SW_Ver_Byte14_16 : 48|8@1+ (1,0) [0|255] ""  PC
 SG_ D2P_Cfg2_SW_Ver_Byte15_16 : 56|8@1+ (1,0) [0|255] ""  PC

BO_ 2499931729 D2P_Cfg2__17: 8 DCDC
 SG_ D2P_Cfg2_SW_Ver_Byte8_17 : 0|8@1+ (1,0) [0|255] ""  PC
 SG_ D2P_Cfg2_SW_Ver_Byte9_17 : 8|8@1+ (1,0) [0|255] ""  PC
 SG_ D2P_Cfg2_SW_Ver_Byte10_17 : 16|8@1+ (1,0) [0|255] ""  PC
 SG_ D2P_Cfg2_SW_Ver_Byte11_17 : 24|8@1+ (1,0) [0|255] ""  PC
 SG_ D2P_Cfg2_SW_Ver_Byte12_17 : 32|8@1+ (1,0) [0|255] ""  PC
 SG_ D2P_Cfg2_SW_Ver_Byte13_17 : 40|8@1+ (1,0) [0|255] ""  PC
 SG_ D2P_Cfg2_SW_Ver_Byte14_17 : 48|8@1+ (1,0) [0|255] ""  PC
 SG_ D2P_Cfg2_SW_Ver_Byte15_17 : 56|8@1+ (1,0) [0|255] ""  PC

BO_ 2499931730 D2P_Cfg2__18: 8 DCDC
 SG_ D2P_Cfg2_SW_Ver_Byte8_18 : 0|8@1+ (1,0) [0|255] ""  PC
 SG_ D2P_Cfg2_SW_Ver_Byte9_18 : 8|8@1+ (1,0) [0|255] ""  PC
 SG_ D2P_Cfg2_SW_Ver_Byte10_18 : 16|8@1+ (1,0) [0|255] ""  PC
 SG_ D2P_Cfg2_SW_Ver_Byte11_18 : 24|8@1+ (1,0) [0|255] ""  PC
 SG_ D2P_Cfg2_SW_Ver_Byte12_18 : 32|8@1+ (1,0) [0|255] ""  PC
 SG_ D2P_Cfg2_SW_Ver_Byte13_18 : 40|8@1+ (1,0) [0|255] ""  PC
 SG_ D2P_Cfg2_SW_Ver_Byte14_18 : 48|8@1+ (1,0) [0|255] ""  PC
 SG_ D2P_Cfg2_SW_Ver_Byte15_18 : 56|8@1+ (1,0) [0|255] ""  PC

BO_ 2499931731 D2P_Cfg2__19: 8 DCDC
 SG_ D2P_Cfg2_SW_Ver_Byte8_19 : 0|8@1+ (1,0) [0|255] ""  PC
 SG_ D2P_Cfg2_SW_Ver_Byte9_19 : 8|8@1+ (1,0) [0|255] ""  PC
 SG_ D2P_Cfg2_SW_Ver_Byte10_19 : 16|8@1+ (1,0) [0|255] ""  PC
 SG_ D2P_Cfg2_SW_Ver_Byte11_19 : 24|8@1+ (1,0) [0|255] ""  PC
 SG_ D2P_Cfg2_SW_Ver_Byte12_19 : 32|8@1+ (1,0) [0|255] ""  PC
 SG_ D2P_Cfg2_SW_Ver_Byte13_19 : 40|8@1+ (1,0) [0|255] ""  PC
 SG_ D2P_Cfg2_SW_Ver_Byte14_19 : 48|8@1+ (1,0) [0|255] ""  PC
 SG_ D2P_Cfg2_SW_Ver_Byte15_19 : 56|8@1+ (1,0) [0|255] ""  PC

BO_ 2499931732 D2P_Cfg2__20: 8 DCDC
 SG_ D2P_Cfg2_SW_Ver_Byte8_20 : 0|8@1+ (1,0) [0|255] ""  PC
 SG_ D2P_Cfg2_SW_Ver_Byte9_20 : 8|8@1+ (1,0) [0|255] ""  PC
 SG_ D2P_Cfg2_SW_Ver_Byte10_20 : 16|8@1+ (1,0) [0|255] ""  PC
 SG_ D2P_Cfg2_SW_Ver_Byte11_20 : 24|8@1+ (1,0) [0|255] ""  PC
 SG_ D2P_Cfg2_SW_Ver_Byte12_20 : 32|8@1+ (1,0) [0|255] ""  PC
 SG_ D2P_Cfg2_SW_Ver_Byte13_20 : 40|8@1+ (1,0) [0|255] ""  PC
 SG_ D2P_Cfg2_SW_Ver_Byte14_20 : 48|8@1+ (1,0) [0|255] ""  PC
 SG_ D2P_Cfg2_SW_Ver_Byte15_20 : 56|8@1+ (1,0) [0|255] ""  PC

BO_ 2499931733 D2P_Cfg2__21: 8 DCDC
 SG_ D2P_Cfg2_SW_Ver_Byte8_21 : 0|8@1+ (1,0) [0|255] ""  PC
 SG_ D2P_Cfg2_SW_Ver_Byte9_21 : 8|8@1+ (1,0) [0|255] ""  PC
 SG_ D2P_Cfg2_SW_Ver_Byte10_21 : 16|8@1+ (1,0) [0|255] ""  PC
 SG_ D2P_Cfg2_SW_Ver_Byte11_21 : 24|8@1+ (1,0) [0|255] ""  PC
 SG_ D2P_Cfg2_SW_Ver_Byte12_21 : 32|8@1+ (1,0) [0|255] ""  PC
 SG_ D2P_Cfg2_SW_Ver_Byte13_21 : 40|8@1+ (1,0) [0|255] ""  PC
 SG_ D2P_Cfg2_SW_Ver_Byte14_21 : 48|8@1+ (1,0) [0|255] ""  PC
 SG_ D2P_Cfg2_SW_Ver_Byte15_21 : 56|8@1+ (1,0) [0|255] ""  PC

BO_ 2499931734 D2P_Cfg2__22: 8 DCDC
 SG_ D2P_Cfg2_SW_Ver_Byte8_22 : 0|8@1+ (1,0) [0|255] ""  PC
 SG_ D2P_Cfg2_SW_Ver_Byte9_22 : 8|8@1+ (1,0) [0|255] ""  PC
 SG_ D2P_Cfg2_SW_Ver_Byte10_22 : 16|8@1+ (1,0) [0|255] ""  PC
 SG_ D2P_Cfg2_SW_Ver_Byte11_22 : 24|8@1+ (1,0) [0|255] ""  PC
 SG_ D2P_Cfg2_SW_Ver_Byte12_22 : 32|8@1+ (1,0) [0|255] ""  PC
 SG_ D2P_Cfg2_SW_Ver_Byte13_22 : 40|8@1+ (1,0) [0|255] ""  PC
 SG_ D2P_Cfg2_SW_Ver_Byte14_22 : 48|8@1+ (1,0) [0|255] ""  PC
 SG_ D2P_Cfg2_SW_Ver_Byte15_22 : 56|8@1+ (1,0) [0|255] ""  PC

BO_ 2499931735 D2P_Cfg2__23: 8 DCDC
 SG_ D2P_Cfg2_SW_Ver_Byte8_23 : 0|8@1+ (1,0) [0|255] ""  PC
 SG_ D2P_Cfg2_SW_Ver_Byte9_23 : 8|8@1+ (1,0) [0|255] ""  PC
 SG_ D2P_Cfg2_SW_Ver_Byte10_23 : 16|8@1+ (1,0) [0|255] ""  PC
 SG_ D2P_Cfg2_SW_Ver_Byte11_23 : 24|8@1+ (1,0) [0|255] ""  PC
 SG_ D2P_Cfg2_SW_Ver_Byte12_23 : 32|8@1+ (1,0) [0|255] ""  PC
 SG_ D2P_Cfg2_SW_Ver_Byte13_23 : 40|8@1+ (1,0) [0|255] ""  PC
 SG_ D2P_Cfg2_SW_Ver_Byte14_23 : 48|8@1+ (1,0) [0|255] ""  PC
 SG_ D2P_Cfg2_SW_Ver_Byte15_23 : 56|8@1+ (1,0) [0|255] ""  PC

BO_ 2499931736 D2P_Cfg2__24: 8 DCDC
 SG_ D2P_Cfg2_SW_Ver_Byte8_24 : 0|8@1+ (1,0) [0|255] ""  PC
 SG_ D2P_Cfg2_SW_Ver_Byte9_24 : 8|8@1+ (1,0) [0|255] ""  PC
 SG_ D2P_Cfg2_SW_Ver_Byte10_24 : 16|8@1+ (1,0) [0|255] ""  PC
 SG_ D2P_Cfg2_SW_Ver_Byte11_24 : 24|8@1+ (1,0) [0|255] ""  PC
 SG_ D2P_Cfg2_SW_Ver_Byte12_24 : 32|8@1+ (1,0) [0|255] ""  PC
 SG_ D2P_Cfg2_SW_Ver_Byte13_24 : 40|8@1+ (1,0) [0|255] ""  PC
 SG_ D2P_Cfg2_SW_Ver_Byte14_24 : 48|8@1+ (1,0) [0|255] ""  PC
 SG_ D2P_Cfg2_SW_Ver_Byte15_24 : 56|8@1+ (1,0) [0|255] ""  PC

BO_ 2499931737 D2P_Cfg2__25: 8 DCDC
 SG_ D2P_Cfg2_SW_Ver_Byte8_25 : 0|8@1+ (1,0) [0|255] ""  PC
 SG_ D2P_Cfg2_SW_Ver_Byte9_25 : 8|8@1+ (1,0) [0|255] ""  PC
 SG_ D2P_Cfg2_SW_Ver_Byte10_25 : 16|8@1+ (1,0) [0|255] ""  PC
 SG_ D2P_Cfg2_SW_Ver_Byte11_25 : 24|8@1+ (1,0) [0|255] ""  PC
 SG_ D2P_Cfg2_SW_Ver_Byte12_25 : 32|8@1+ (1,0) [0|255] ""  PC
 SG_ D2P_Cfg2_SW_Ver_Byte13_25 : 40|8@1+ (1,0) [0|255] ""  PC
 SG_ D2P_Cfg2_SW_Ver_Byte14_25 : 48|8@1+ (1,0) [0|255] ""  PC
 SG_ D2P_Cfg2_SW_Ver_Byte15_25 : 56|8@1+ (1,0) [0|255] ""  PC

BO_ 2499931738 D2P_Cfg2__26: 8 DCDC
 SG_ D2P_Cfg2_SW_Ver_Byte8_26 : 0|8@1+ (1,0) [0|255] ""  PC
 SG_ D2P_Cfg2_SW_Ver_Byte9_26 : 8|8@1+ (1,0) [0|255] ""  PC
 SG_ D2P_Cfg2_SW_Ver_Byte10_26 : 16|8@1+ (1,0) [0|255] ""  PC
 SG_ D2P_Cfg2_SW_Ver_Byte11_26 : 24|8@1+ (1,0) [0|255] ""  PC
 SG_ D2P_Cfg2_SW_Ver_Byte12_26 : 32|8@1+ (1,0) [0|255] ""  PC
 SG_ D2P_Cfg2_SW_Ver_Byte13_26 : 40|8@1+ (1,0) [0|255] ""  PC
 SG_ D2P_Cfg2_SW_Ver_Byte14_26 : 48|8@1+ (1,0) [0|255] ""  PC
 SG_ D2P_Cfg2_SW_Ver_Byte15_26 : 56|8@1+ (1,0) [0|255] ""  PC

BO_ 2499931739 D2P_Cfg2__27: 8 DCDC
 SG_ D2P_Cfg2_SW_Ver_Byte8_27 : 0|8@1+ (1,0) [0|255] ""  PC
 SG_ D2P_Cfg2_SW_Ver_Byte9_27 : 8|8@1+ (1,0) [0|255] ""  PC
 SG_ D2P_Cfg2_SW_Ver_Byte10_27 : 16|8@1+ (1,0) [0|255] ""  PC
 SG_ D2P_Cfg2_SW_Ver_Byte11_27 : 24|8@1+ (1,0) [0|255] ""  PC
 SG_ D2P_Cfg2_SW_Ver_Byte12_27 : 32|8@1+ (1,0) [0|255] ""  PC
 SG_ D2P_Cfg2_SW_Ver_Byte13_27 : 40|8@1+ (1,0) [0|255] ""  PC
 SG_ D2P_Cfg2_SW_Ver_Byte14_27 : 48|8@1+ (1,0) [0|255] ""  PC
 SG_ D2P_Cfg2_SW_Ver_Byte15_27 : 56|8@1+ (1,0) [0|255] ""  PC

BO_ 2499931740 D2P_Cfg2__28: 8 DCDC
 SG_ D2P_Cfg2_SW_Ver_Byte8_28 : 0|8@1+ (1,0) [0|255] ""  PC
 SG_ D2P_Cfg2_SW_Ver_Byte9_28 : 8|8@1+ (1,0) [0|255] ""  PC
 SG_ D2P_Cfg2_SW_Ver_Byte10_28 : 16|8@1+ (1,0) [0|255] ""  PC
 SG_ D2P_Cfg2_SW_Ver_Byte11_28 : 24|8@1+ (1,0) [0|255] ""  PC
 SG_ D2P_Cfg2_SW_Ver_Byte12_28 : 32|8@1+ (1,0) [0|255] ""  PC
 SG_ D2P_Cfg2_SW_Ver_Byte13_28 : 40|8@1+ (1,0) [0|255] ""  PC
 SG_ D2P_Cfg2_SW_Ver_Byte14_28 : 48|8@1+ (1,0) [0|255] ""  PC
 SG_ D2P_Cfg2_SW_Ver_Byte15_28 : 56|8@1+ (1,0) [0|255] ""  PC

BO_ 2499931741 D2P_Cfg2__29: 8 DCDC
 SG_ D2P_Cfg2_SW_Ver_Byte8_29 : 0|8@1+ (1,0) [0|255] ""  PC
 SG_ D2P_Cfg2_SW_Ver_Byte9_29 : 8|8@1+ (1,0) [0|255] ""  PC
 SG_ D2P_Cfg2_SW_Ver_Byte10_29 : 16|8@1+ (1,0) [0|255] ""  PC
 SG_ D2P_Cfg2_SW_Ver_Byte11_29 : 24|8@1+ (1,0) [0|255] ""  PC
 SG_ D2P_Cfg2_SW_Ver_Byte12_29 : 32|8@1+ (1,0) [0|255] ""  PC
 SG_ D2P_Cfg2_SW_Ver_Byte13_29 : 40|8@1+ (1,0) [0|255] ""  PC
 SG_ D2P_Cfg2_SW_Ver_Byte14_29 : 48|8@1+ (1,0) [0|255] ""  PC
 SG_ D2P_Cfg2_SW_Ver_Byte15_29 : 56|8@1+ (1,0) [0|255] ""  PC

BO_ 2499931742 D2P_Cfg2__30: 8 DCDC
 SG_ D2P_Cfg2_SW_Ver_Byte8_30 : 0|8@1+ (1,0) [0|255] ""  PC
 SG_ D2P_Cfg2_SW_Ver_Byte9_30 : 8|8@1+ (1,0) [0|255] ""  PC
 SG_ D2P_Cfg2_SW_Ver_Byte10_30 : 16|8@1+ (1,0) [0|255] ""  PC
 SG_ D2P_Cfg2_SW_Ver_Byte11_30 : 24|8@1+ (1,0) [0|255] ""  PC
 SG_ D2P_Cfg2_SW_Ver_Byte12_30 : 32|8@1+ (1,0) [0|255] ""  PC
 SG_ D2P_Cfg2_SW_Ver_Byte13_30 : 40|8@1+ (1,0) [0|255] ""  PC
 SG_ D2P_Cfg2_SW_Ver_Byte14_30 : 48|8@1+ (1,0) [0|255] ""  PC
 SG_ D2P_Cfg2_SW_Ver_Byte15_30 : 56|8@1+ (1,0) [0|255] ""  PC

BO_ 2499931743 D2P_Cfg2__31: 8 DCDC
 SG_ D2P_Cfg2_SW_Ver_Byte8_31 : 0|8@1+ (1,0) [0|255] ""  PC
 SG_ D2P_Cfg2_SW_Ver_Byte9_31 : 8|8@1+ (1,0) [0|255] ""  PC
 SG_ D2P_Cfg2_SW_Ver_Byte10_31 : 16|8@1+ (1,0) [0|255] ""  PC
 SG_ D2P_Cfg2_SW_Ver_Byte11_31 : 24|8@1+ (1,0) [0|255] ""  PC
 SG_ D2P_Cfg2_SW_Ver_Byte12_31 : 32|8@1+ (1,0) [0|255] ""  PC
 SG_ D2P_Cfg2_SW_Ver_Byte13_31 : 40|8@1+ (1,0) [0|255] ""  PC
 SG_ D2P_Cfg2_SW_Ver_Byte14_31 : 48|8@1+ (1,0) [0|255] ""  PC
 SG_ D2P_Cfg2_SW_Ver_Byte15_31 : 56|8@1+ (1,0) [0|255] ""  PC

BO_ 2499931744 D2P_Cfg2__32: 8 DCDC
 SG_ D2P_Cfg2_SW_Ver_Byte8_32 : 0|8@1+ (1,0) [0|255] ""  PC
 SG_ D2P_Cfg2_SW_Ver_Byte9_32 : 8|8@1+ (1,0) [0|255] ""  PC
 SG_ D2P_Cfg2_SW_Ver_Byte10_32 : 16|8@1+ (1,0) [0|255] ""  PC
 SG_ D2P_Cfg2_SW_Ver_Byte11_32 : 24|8@1+ (1,0) [0|255] ""  PC
 SG_ D2P_Cfg2_SW_Ver_Byte12_32 : 32|8@1+ (1,0) [0|255] ""  PC
 SG_ D2P_Cfg2_SW_Ver_Byte13_32 : 40|8@1+ (1,0) [0|255] ""  PC
 SG_ D2P_Cfg2_SW_Ver_Byte14_32 : 48|8@1+ (1,0) [0|255] ""  PC
 SG_ D2P_Cfg2_SW_Ver_Byte15_32 : 56|8@1+ (1,0) [0|255] ""  PC

BO_ 2499931745 D2P_Cfg2__33: 8 DCDC
 SG_ D2P_Cfg2_SW_Ver_Byte8_33 : 0|8@1+ (1,0) [0|255] ""  PC
 SG_ D2P_Cfg2_SW_Ver_Byte9_33 : 8|8@1+ (1,0) [0|255] ""  PC
 SG_ D2P_Cfg2_SW_Ver_Byte10_33 : 16|8@1+ (1,0) [0|255] ""  PC
 SG_ D2P_Cfg2_SW_Ver_Byte11_33 : 24|8@1+ (1,0) [0|255] ""  PC
 SG_ D2P_Cfg2_SW_Ver_Byte12_33 : 32|8@1+ (1,0) [0|255] ""  PC
 SG_ D2P_Cfg2_SW_Ver_Byte13_33 : 40|8@1+ (1,0) [0|255] ""  PC
 SG_ D2P_Cfg2_SW_Ver_Byte14_33 : 48|8@1+ (1,0) [0|255] ""  PC
 SG_ D2P_Cfg2_SW_Ver_Byte15_33 : 56|8@1+ (1,0) [0|255] ""  PC

BO_ 2499931746 D2P_Cfg2__34: 8 DCDC
 SG_ D2P_Cfg2_SW_Ver_Byte8_34 : 0|8@1+ (1,0) [0|255] ""  PC
 SG_ D2P_Cfg2_SW_Ver_Byte9_34 : 8|8@1+ (1,0) [0|255] ""  PC
 SG_ D2P_Cfg2_SW_Ver_Byte10_34 : 16|8@1+ (1,0) [0|255] ""  PC
 SG_ D2P_Cfg2_SW_Ver_Byte11_34 : 24|8@1+ (1,0) [0|255] ""  PC
 SG_ D2P_Cfg2_SW_Ver_Byte12_34 : 32|8@1+ (1,0) [0|255] ""  PC
 SG_ D2P_Cfg2_SW_Ver_Byte13_34 : 40|8@1+ (1,0) [0|255] ""  PC
 SG_ D2P_Cfg2_SW_Ver_Byte14_34 : 48|8@1+ (1,0) [0|255] ""  PC
 SG_ D2P_Cfg2_SW_Ver_Byte15_34 : 56|8@1+ (1,0) [0|255] ""  PC

BO_ 2499931747 D2P_Cfg2__35: 8 DCDC
 SG_ D2P_Cfg2_SW_Ver_Byte8_35 : 0|8@1+ (1,0) [0|255] ""  PC
 SG_ D2P_Cfg2_SW_Ver_Byte9_35 : 8|8@1+ (1,0) [0|255] ""  PC
 SG_ D2P_Cfg2_SW_Ver_Byte10_35 : 16|8@1+ (1,0) [0|255] ""  PC
 SG_ D2P_Cfg2_SW_Ver_Byte11_35 : 24|8@1+ (1,0) [0|255] ""  PC
 SG_ D2P_Cfg2_SW_Ver_Byte12_35 : 32|8@1+ (1,0) [0|255] ""  PC
 SG_ D2P_Cfg2_SW_Ver_Byte13_35 : 40|8@1+ (1,0) [0|255] ""  PC
 SG_ D2P_Cfg2_SW_Ver_Byte14_35 : 48|8@1+ (1,0) [0|255] ""  PC
 SG_ D2P_Cfg2_SW_Ver_Byte15_35 : 56|8@1+ (1,0) [0|255] ""  PC

BO_ 2499931748 D2P_Cfg2__36: 8 DCDC
 SG_ D2P_Cfg2_SW_Ver_Byte8_36 : 0|8@1+ (1,0) [0|255] ""  PC
 SG_ D2P_Cfg2_SW_Ver_Byte9_36 : 8|8@1+ (1,0) [0|255] ""  PC
 SG_ D2P_Cfg2_SW_Ver_Byte10_36 : 16|8@1+ (1,0) [0|255] ""  PC
 SG_ D2P_Cfg2_SW_Ver_Byte11_36 : 24|8@1+ (1,0) [0|255] ""  PC
 SG_ D2P_Cfg2_SW_Ver_Byte12_36 : 32|8@1+ (1,0) [0|255] ""  PC
 SG_ D2P_Cfg2_SW_Ver_Byte13_36 : 40|8@1+ (1,0) [0|255] ""  PC
 SG_ D2P_Cfg2_SW_Ver_Byte14_36 : 48|8@1+ (1,0) [0|255] ""  PC
 SG_ D2P_Cfg2_SW_Ver_Byte15_36 : 56|8@1+ (1,0) [0|255] ""  PC

BO_ 2499931749 D2P_Cfg2__37: 8 DCDC
 SG_ D2P_Cfg2_SW_Ver_Byte8_37 : 0|8@1+ (1,0) [0|255] ""  PC
 SG_ D2P_Cfg2_SW_Ver_Byte9_37 : 8|8@1+ (1,0) [0|255] ""  PC
 SG_ D2P_Cfg2_SW_Ver_Byte10_37 : 16|8@1+ (1,0) [0|255] ""  PC
 SG_ D2P_Cfg2_SW_Ver_Byte11_37 : 24|8@1+ (1,0) [0|255] ""  PC
 SG_ D2P_Cfg2_SW_Ver_Byte12_37 : 32|8@1+ (1,0) [0|255] ""  PC
 SG_ D2P_Cfg2_SW_Ver_Byte13_37 : 40|8@1+ (1,0) [0|255] ""  PC
 SG_ D2P_Cfg2_SW_Ver_Byte14_37 : 48|8@1+ (1,0) [0|255] ""  PC
 SG_ D2P_Cfg2_SW_Ver_Byte15_37 : 56|8@1+ (1,0) [0|255] ""  PC

BO_ 2499931750 D2P_Cfg2__38: 8 DCDC
 SG_ D2P_Cfg2_SW_Ver_Byte8_38 : 0|8@1+ (1,0) [0|255] ""  PC
 SG_ D2P_Cfg2_SW_Ver_Byte9_38 : 8|8@1+ (1,0) [0|255] ""  PC
 SG_ D2P_Cfg2_SW_Ver_Byte10_38 : 16|8@1+ (1,0) [0|255] ""  PC
 SG_ D2P_Cfg2_SW_Ver_Byte11_38 : 24|8@1+ (1,0) [0|255] ""  PC
 SG_ D2P_Cfg2_SW_Ver_Byte12_38 : 32|8@1+ (1,0) [0|255] ""  PC
 SG_ D2P_Cfg2_SW_Ver_Byte13_38 : 40|8@1+ (1,0) [0|255] ""  PC
 SG_ D2P_Cfg2_SW_Ver_Byte14_38 : 48|8@1+ (1,0) [0|255] ""  PC
 SG_ D2P_Cfg2_SW_Ver_Byte15_38 : 56|8@1+ (1,0) [0|255] ""  PC

BO_ 2499931751 D2P_Cfg2__39: 8 DCDC
 SG_ D2P_Cfg2_SW_Ver_Byte8_39 : 0|8@1+ (1,0) [0|255] ""  PC
 SG_ D2P_Cfg2_SW_Ver_Byte9_39 : 8|8@1+ (1,0) [0|255] ""  PC
 SG_ D2P_Cfg2_SW_Ver_Byte10_39 : 16|8@1+ (1,0) [0|255] ""  PC
 SG_ D2P_Cfg2_SW_Ver_Byte11_39 : 24|8@1+ (1,0) [0|255] ""  PC
 SG_ D2P_Cfg2_SW_Ver_Byte12_39 : 32|8@1+ (1,0) [0|255] ""  PC
 SG_ D2P_Cfg2_SW_Ver_Byte13_39 : 40|8@1+ (1,0) [0|255] ""  PC
 SG_ D2P_Cfg2_SW_Ver_Byte14_39 : 48|8@1+ (1,0) [0|255] ""  PC
 SG_ D2P_Cfg2_SW_Ver_Byte15_39 : 56|8@1+ (1,0) [0|255] ""  PC

BO_ 2499931752 D2P_Cfg2__40: 8 DCDC
 SG_ D2P_Cfg2_SW_Ver_Byte8_40 : 0|8@1+ (1,0) [0|255] ""  PC
 SG_ D2P_Cfg2_SW_Ver_Byte9_40 : 8|8@1+ (1,0) [0|255] ""  PC
 SG_ D2P_Cfg2_SW_Ver_Byte10_40 : 16|8@1+ (1,0) [0|255] ""  PC
 SG_ D2P_Cfg2_SW_Ver_Byte11_40 : 24|8@1+ (1,0) [0|255] ""  PC
 SG_ D2P_Cfg2_SW_Ver_Byte12_40 : 32|8@1+ (1,0) [0|255] ""  PC
 SG_ D2P_Cfg2_SW_Ver_Byte13_40 : 40|8@1+ (1,0) [0|255] ""  PC
 SG_ D2P_Cfg2_SW_Ver_Byte14_40 : 48|8@1+ (1,0) [0|255] ""  PC
 SG_ D2P_Cfg2_SW_Ver_Byte15_40 : 56|8@1+ (1,0) [0|255] ""  PC

BO_ 2499931753 D2P_Cfg2__41: 8 DCDC
 SG_ D2P_Cfg2_SW_Ver_Byte8_41 : 0|8@1+ (1,0) [0|255] ""  PC
 SG_ D2P_Cfg2_SW_Ver_Byte9_41 : 8|8@1+ (1,0) [0|255] ""  PC
 SG_ D2P_Cfg2_SW_Ver_Byte10_41 : 16|8@1+ (1,0) [0|255] ""  PC
 SG_ D2P_Cfg2_SW_Ver_Byte11_41 : 24|8@1+ (1,0) [0|255] ""  PC
 SG_ D2P_Cfg2_SW_Ver_Byte12_41 : 32|8@1+ (1,0) [0|255] ""  PC
 SG_ D2P_Cfg2_SW_Ver_Byte13_41 : 40|8@1+ (1,0) [0|255] ""  PC
 SG_ D2P_Cfg2_SW_Ver_Byte14_41 : 48|8@1+ (1,0) [0|255] ""  PC
 SG_ D2P_Cfg2_SW_Ver_Byte15_41 : 56|8@1+ (1,0) [0|255] ""  PC

BO_ 2499931754 D2P_Cfg2__42: 8 DCDC
 SG_ D2P_Cfg2_SW_Ver_Byte8_42 : 0|8@1+ (1,0) [0|255] ""  PC
 SG_ D2P_Cfg2_SW_Ver_Byte9_42 : 8|8@1+ (1,0) [0|255] ""  PC
 SG_ D2P_Cfg2_SW_Ver_Byte10_42 : 16|8@1+ (1,0) [0|255] ""  PC
 SG_ D2P_Cfg2_SW_Ver_Byte11_42 : 24|8@1+ (1,0) [0|255] ""  PC
 SG_ D2P_Cfg2_SW_Ver_Byte12_42 : 32|8@1+ (1,0) [0|255] ""  PC
 SG_ D2P_Cfg2_SW_Ver_Byte13_42 : 40|8@1+ (1,0) [0|255] ""  PC
 SG_ D2P_Cfg2_SW_Ver_Byte14_42 : 48|8@1+ (1,0) [0|255] ""  PC
 SG_ D2P_Cfg2_SW_Ver_Byte15_42 : 56|8@1+ (1,0) [0|255] ""  PC

BO_ 2499931755 D2P_Cfg2__43: 8 DCDC
 SG_ D2P_Cfg2_SW_Ver_Byte8_43 : 0|8@1+ (1,0) [0|255] ""  PC
 SG_ D2P_Cfg2_SW_Ver_Byte9_43 : 8|8@1+ (1,0) [0|255] ""  PC
 SG_ D2P_Cfg2_SW_Ver_Byte10_43 : 16|8@1+ (1,0) [0|255] ""  PC
 SG_ D2P_Cfg2_SW_Ver_Byte11_43 : 24|8@1+ (1,0) [0|255] ""  PC
 SG_ D2P_Cfg2_SW_Ver_Byte12_43 : 32|8@1+ (1,0) [0|255] ""  PC
 SG_ D2P_Cfg2_SW_Ver_Byte13_43 : 40|8@1+ (1,0) [0|255] ""  PC
 SG_ D2P_Cfg2_SW_Ver_Byte14_43 : 48|8@1+ (1,0) [0|255] ""  PC
 SG_ D2P_Cfg2_SW_Ver_Byte15_43 : 56|8@1+ (1,0) [0|255] ""  PC

BO_ 2499931756 D2P_Cfg2__44: 8 DCDC
 SG_ D2P_Cfg2_SW_Ver_Byte8_44 : 0|8@1+ (1,0) [0|255] ""  PC
 SG_ D2P_Cfg2_SW_Ver_Byte9_44 : 8|8@1+ (1,0) [0|255] ""  PC
 SG_ D2P_Cfg2_SW_Ver_Byte10_44 : 16|8@1+ (1,0) [0|255] ""  PC
 SG_ D2P_Cfg2_SW_Ver_Byte11_44 : 24|8@1+ (1,0) [0|255] ""  PC
 SG_ D2P_Cfg2_SW_Ver_Byte12_44 : 32|8@1+ (1,0) [0|255] ""  PC
 SG_ D2P_Cfg2_SW_Ver_Byte13_44 : 40|8@1+ (1,0) [0|255] ""  PC
 SG_ D2P_Cfg2_SW_Ver_Byte14_44 : 48|8@1+ (1,0) [0|255] ""  PC
 SG_ D2P_Cfg2_SW_Ver_Byte15_44 : 56|8@1+ (1,0) [0|255] ""  PC

BO_ 2499931757 D2P_Cfg2__45: 8 DCDC
 SG_ D2P_Cfg2_SW_Ver_Byte8_45 : 0|8@1+ (1,0) [0|255] ""  PC
 SG_ D2P_Cfg2_SW_Ver_Byte9_45 : 8|8@1+ (1,0) [0|255] ""  PC
 SG_ D2P_Cfg2_SW_Ver_Byte10_45 : 16|8@1+ (1,0) [0|255] ""  PC
 SG_ D2P_Cfg2_SW_Ver_Byte11_45 : 24|8@1+ (1,0) [0|255] ""  PC
 SG_ D2P_Cfg2_SW_Ver_Byte12_45 : 32|8@1+ (1,0) [0|255] ""  PC
 SG_ D2P_Cfg2_SW_Ver_Byte13_45 : 40|8@1+ (1,0) [0|255] ""  PC
 SG_ D2P_Cfg2_SW_Ver_Byte14_45 : 48|8@1+ (1,0) [0|255] ""  PC
 SG_ D2P_Cfg2_SW_Ver_Byte15_45 : 56|8@1+ (1,0) [0|255] ""  PC

BO_ 2499931758 D2P_Cfg2__46: 8 DCDC
 SG_ D2P_Cfg2_SW_Ver_Byte8_46 : 0|8@1+ (1,0) [0|255] ""  PC
 SG_ D2P_Cfg2_SW_Ver_Byte9_46 : 8|8@1+ (1,0) [0|255] ""  PC
 SG_ D2P_Cfg2_SW_Ver_Byte10_46 : 16|8@1+ (1,0) [0|255] ""  PC
 SG_ D2P_Cfg2_SW_Ver_Byte11_46 : 24|8@1+ (1,0) [0|255] ""  PC
 SG_ D2P_Cfg2_SW_Ver_Byte12_46 : 32|8@1+ (1,0) [0|255] ""  PC
 SG_ D2P_Cfg2_SW_Ver_Byte13_46 : 40|8@1+ (1,0) [0|255] ""  PC
 SG_ D2P_Cfg2_SW_Ver_Byte14_46 : 48|8@1+ (1,0) [0|255] ""  PC
 SG_ D2P_Cfg2_SW_Ver_Byte15_46 : 56|8@1+ (1,0) [0|255] ""  PC

BO_ 2499931759 D2P_Cfg2__47: 8 DCDC
 SG_ D2P_Cfg2_SW_Ver_Byte8_47 : 0|8@1+ (1,0) [0|255] ""  PC
 SG_ D2P_Cfg2_SW_Ver_Byte9_47 : 8|8@1+ (1,0) [0|255] ""  PC
 SG_ D2P_Cfg2_SW_Ver_Byte10_47 : 16|8@1+ (1,0) [0|255] ""  PC
 SG_ D2P_Cfg2_SW_Ver_Byte11_47 : 24|8@1+ (1,0) [0|255] ""  PC
 SG_ D2P_Cfg2_SW_Ver_Byte12_47 : 32|8@1+ (1,0) [0|255] ""  PC
 SG_ D2P_Cfg2_SW_Ver_Byte13_47 : 40|8@1+ (1,0) [0|255] ""  PC
 SG_ D2P_Cfg2_SW_Ver_Byte14_47 : 48|8@1+ (1,0) [0|255] ""  PC
 SG_ D2P_Cfg2_SW_Ver_Byte15_47 : 56|8@1+ (1,0) [0|255] ""  PC

BO_ 2499931760 D2P_Cfg2__48: 8 DCDC
 SG_ D2P_Cfg2_SW_Ver_Byte8_48 : 0|8@1+ (1,0) [0|255] ""  PC
 SG_ D2P_Cfg2_SW_Ver_Byte9_48 : 8|8@1+ (1,0) [0|255] ""  PC
 SG_ D2P_Cfg2_SW_Ver_Byte10_48 : 16|8@1+ (1,0) [0|255] ""  PC
 SG_ D2P_Cfg2_SW_Ver_Byte11_48 : 24|8@1+ (1,0) [0|255] ""  PC
 SG_ D2P_Cfg2_SW_Ver_Byte12_48 : 32|8@1+ (1,0) [0|255] ""  PC
 SG_ D2P_Cfg2_SW_Ver_Byte13_48 : 40|8@1+ (1,0) [0|255] ""  PC
 SG_ D2P_Cfg2_SW_Ver_Byte14_48 : 48|8@1+ (1,0) [0|255] ""  PC
 SG_ D2P_Cfg2_SW_Ver_Byte15_48 : 56|8@1+ (1,0) [0|255] ""  PC

BO_ 2499931761 D2P_Cfg2__49: 8 DCDC
 SG_ D2P_Cfg2_SW_Ver_Byte8_49 : 0|8@1+ (1,0) [0|255] ""  PC
 SG_ D2P_Cfg2_SW_Ver_Byte9_49 : 8|8@1+ (1,0) [0|255] ""  PC
 SG_ D2P_Cfg2_SW_Ver_Byte10_49 : 16|8@1+ (1,0) [0|255] ""  PC
 SG_ D2P_Cfg2_SW_Ver_Byte11_49 : 24|8@1+ (1,0) [0|255] ""  PC
 SG_ D2P_Cfg2_SW_Ver_Byte12_49 : 32|8@1+ (1,0) [0|255] ""  PC
 SG_ D2P_Cfg2_SW_Ver_Byte13_49 : 40|8@1+ (1,0) [0|255] ""  PC
 SG_ D2P_Cfg2_SW_Ver_Byte14_49 : 48|8@1+ (1,0) [0|255] ""  PC
 SG_ D2P_Cfg2_SW_Ver_Byte15_49 : 56|8@1+ (1,0) [0|255] ""  PC

BO_ 2499931762 D2P_Cfg2__50: 8 DCDC
 SG_ D2P_Cfg2_SW_Ver_Byte8_50 : 0|8@1+ (1,0) [0|255] ""  PC
 SG_ D2P_Cfg2_SW_Ver_Byte9_50 : 8|8@1+ (1,0) [0|255] ""  PC
 SG_ D2P_Cfg2_SW_Ver_Byte10_50 : 16|8@1+ (1,0) [0|255] ""  PC
 SG_ D2P_Cfg2_SW_Ver_Byte11_50 : 24|8@1+ (1,0) [0|255] ""  PC
 SG_ D2P_Cfg2_SW_Ver_Byte12_50 : 32|8@1+ (1,0) [0|255] ""  PC
 SG_ D2P_Cfg2_SW_Ver_Byte13_50 : 40|8@1+ (1,0) [0|255] ""  PC
 SG_ D2P_Cfg2_SW_Ver_Byte14_50 : 48|8@1+ (1,0) [0|255] ""  PC
 SG_ D2P_Cfg2_SW_Ver_Byte15_50 : 56|8@1+ (1,0) [0|255] ""  PC

BO_ 2499931763 D2P_Cfg2__51: 8 DCDC
 SG_ D2P_Cfg2_SW_Ver_Byte8_51 : 0|8@1+ (1,0) [0|255] ""  PC
 SG_ D2P_Cfg2_SW_Ver_Byte9_51 : 8|8@1+ (1,0) [0|255] ""  PC
 SG_ D2P_Cfg2_SW_Ver_Byte10_51 : 16|8@1+ (1,0) [0|255] ""  PC
 SG_ D2P_Cfg2_SW_Ver_Byte11_51 : 24|8@1+ (1,0) [0|255] ""  PC
 SG_ D2P_Cfg2_SW_Ver_Byte12_51 : 32|8@1+ (1,0) [0|255] ""  PC
 SG_ D2P_Cfg2_SW_Ver_Byte13_51 : 40|8@1+ (1,0) [0|255] ""  PC
 SG_ D2P_Cfg2_SW_Ver_Byte14_51 : 48|8@1+ (1,0) [0|255] ""  PC
 SG_ D2P_Cfg2_SW_Ver_Byte15_51 : 56|8@1+ (1,0) [0|255] ""  PC

BO_ 2499931764 D2P_Cfg2__52: 8 DCDC
 SG_ D2P_Cfg2_SW_Ver_Byte8_52 : 0|8@1+ (1,0) [0|255] ""  PC
 SG_ D2P_Cfg2_SW_Ver_Byte9_52 : 8|8@1+ (1,0) [0|255] ""  PC
 SG_ D2P_Cfg2_SW_Ver_Byte10_52 : 16|8@1+ (1,0) [0|255] ""  PC
 SG_ D2P_Cfg2_SW_Ver_Byte11_52 : 24|8@1+ (1,0) [0|255] ""  PC
 SG_ D2P_Cfg2_SW_Ver_Byte12_52 : 32|8@1+ (1,0) [0|255] ""  PC
 SG_ D2P_Cfg2_SW_Ver_Byte13_52 : 40|8@1+ (1,0) [0|255] ""  PC
 SG_ D2P_Cfg2_SW_Ver_Byte14_52 : 48|8@1+ (1,0) [0|255] ""  PC
 SG_ D2P_Cfg2_SW_Ver_Byte15_52 : 56|8@1+ (1,0) [0|255] ""  PC

BO_ 2499931765 D2P_Cfg2__53: 8 DCDC
 SG_ D2P_Cfg2_SW_Ver_Byte8_53 : 0|8@1+ (1,0) [0|255] ""  PC
 SG_ D2P_Cfg2_SW_Ver_Byte9_53 : 8|8@1+ (1,0) [0|255] ""  PC
 SG_ D2P_Cfg2_SW_Ver_Byte10_53 : 16|8@1+ (1,0) [0|255] ""  PC
 SG_ D2P_Cfg2_SW_Ver_Byte11_53 : 24|8@1+ (1,0) [0|255] ""  PC
 SG_ D2P_Cfg2_SW_Ver_Byte12_53 : 32|8@1+ (1,0) [0|255] ""  PC
 SG_ D2P_Cfg2_SW_Ver_Byte13_53 : 40|8@1+ (1,0) [0|255] ""  PC
 SG_ D2P_Cfg2_SW_Ver_Byte14_53 : 48|8@1+ (1,0) [0|255] ""  PC
 SG_ D2P_Cfg2_SW_Ver_Byte15_53 : 56|8@1+ (1,0) [0|255] ""  PC

BO_ 2499931766 D2P_Cfg2__54: 8 DCDC
 SG_ D2P_Cfg2_SW_Ver_Byte8_54 : 0|8@1+ (1,0) [0|255] ""  PC
 SG_ D2P_Cfg2_SW_Ver_Byte9_54 : 8|8@1+ (1,0) [0|255] ""  PC
 SG_ D2P_Cfg2_SW_Ver_Byte10_54 : 16|8@1+ (1,0) [0|255] ""  PC
 SG_ D2P_Cfg2_SW_Ver_Byte11_54 : 24|8@1+ (1,0) [0|255] ""  PC
 SG_ D2P_Cfg2_SW_Ver_Byte12_54 : 32|8@1+ (1,0) [0|255] ""  PC
 SG_ D2P_Cfg2_SW_Ver_Byte13_54 : 40|8@1+ (1,0) [0|255] ""  PC
 SG_ D2P_Cfg2_SW_Ver_Byte14_54 : 48|8@1+ (1,0) [0|255] ""  PC
 SG_ D2P_Cfg2_SW_Ver_Byte15_54 : 56|8@1+ (1,0) [0|255] ""  PC

BO_ 2499931767 D2P_Cfg2__55: 8 DCDC
 SG_ D2P_Cfg2_SW_Ver_Byte8_55 : 0|8@1+ (1,0) [0|255] ""  PC
 SG_ D2P_Cfg2_SW_Ver_Byte9_55 : 8|8@1+ (1,0) [0|255] ""  PC
 SG_ D2P_Cfg2_SW_Ver_Byte10_55 : 16|8@1+ (1,0) [0|255] ""  PC
 SG_ D2P_Cfg2_SW_Ver_Byte11_55 : 24|8@1+ (1,0) [0|255] ""  PC
 SG_ D2P_Cfg2_SW_Ver_Byte12_55 : 32|8@1+ (1,0) [0|255] ""  PC
 SG_ D2P_Cfg2_SW_Ver_Byte13_55 : 40|8@1+ (1,0) [0|255] ""  PC
 SG_ D2P_Cfg2_SW_Ver_Byte14_55 : 48|8@1+ (1,0) [0|255] ""  PC
 SG_ D2P_Cfg2_SW_Ver_Byte15_55 : 56|8@1+ (1,0) [0|255] ""  PC

BO_ 2499931768 D2P_Cfg2__56: 8 DCDC
 SG_ D2P_Cfg2_SW_Ver_Byte8_56 : 0|8@1+ (1,0) [0|255] ""  PC
 SG_ D2P_Cfg2_SW_Ver_Byte9_56 : 8|8@1+ (1,0) [0|255] ""  PC
 SG_ D2P_Cfg2_SW_Ver_Byte10_56 : 16|8@1+ (1,0) [0|255] ""  PC
 SG_ D2P_Cfg2_SW_Ver_Byte11_56 : 24|8@1+ (1,0) [0|255] ""  PC
 SG_ D2P_Cfg2_SW_Ver_Byte12_56 : 32|8@1+ (1,0) [0|255] ""  PC
 SG_ D2P_Cfg2_SW_Ver_Byte13_56 : 40|8@1+ (1,0) [0|255] ""  PC
 SG_ D2P_Cfg2_SW_Ver_Byte14_56 : 48|8@1+ (1,0) [0|255] ""  PC
 SG_ D2P_Cfg2_SW_Ver_Byte15_56 : 56|8@1+ (1,0) [0|255] ""  PC

BO_ 2499931769 D2P_Cfg2__57: 8 DCDC
 SG_ D2P_Cfg2_SW_Ver_Byte8_57 : 0|8@1+ (1,0) [0|255] ""  PC
 SG_ D2P_Cfg2_SW_Ver_Byte9_57 : 8|8@1+ (1,0) [0|255] ""  PC
 SG_ D2P_Cfg2_SW_Ver_Byte10_57 : 16|8@1+ (1,0) [0|255] ""  PC
 SG_ D2P_Cfg2_SW_Ver_Byte11_57 : 24|8@1+ (1,0) [0|255] ""  PC
 SG_ D2P_Cfg2_SW_Ver_Byte12_57 : 32|8@1+ (1,0) [0|255] ""  PC
 SG_ D2P_Cfg2_SW_Ver_Byte13_57 : 40|8@1+ (1,0) [0|255] ""  PC
 SG_ D2P_Cfg2_SW_Ver_Byte14_57 : 48|8@1+ (1,0) [0|255] ""  PC
 SG_ D2P_Cfg2_SW_Ver_Byte15_57 : 56|8@1+ (1,0) [0|255] ""  PC

BO_ 2499931770 D2P_Cfg2__58: 8 DCDC
 SG_ D2P_Cfg2_SW_Ver_Byte8_58 : 0|8@1+ (1,0) [0|255] ""  PC
 SG_ D2P_Cfg2_SW_Ver_Byte9_58 : 8|8@1+ (1,0) [0|255] ""  PC
 SG_ D2P_Cfg2_SW_Ver_Byte10_58 : 16|8@1+ (1,0) [0|255] ""  PC
 SG_ D2P_Cfg2_SW_Ver_Byte11_58 : 24|8@1+ (1,0) [0|255] ""  PC
 SG_ D2P_Cfg2_SW_Ver_Byte12_58 : 32|8@1+ (1,0) [0|255] ""  PC
 SG_ D2P_Cfg2_SW_Ver_Byte13_58 : 40|8@1+ (1,0) [0|255] ""  PC
 SG_ D2P_Cfg2_SW_Ver_Byte14_58 : 48|8@1+ (1,0) [0|255] ""  PC
 SG_ D2P_Cfg2_SW_Ver_Byte15_58 : 56|8@1+ (1,0) [0|255] ""  PC

BO_ 2499931771 D2P_Cfg2__59: 8 DCDC
 SG_ D2P_Cfg2_SW_Ver_Byte8_59 : 0|8@1+ (1,0) [0|255] ""  PC
 SG_ D2P_Cfg2_SW_Ver_Byte9_59 : 8|8@1+ (1,0) [0|255] ""  PC
 SG_ D2P_Cfg2_SW_Ver_Byte10_59 : 16|8@1+ (1,0) [0|255] ""  PC
 SG_ D2P_Cfg2_SW_Ver_Byte11_59 : 24|8@1+ (1,0) [0|255] ""  PC
 SG_ D2P_Cfg2_SW_Ver_Byte12_59 : 32|8@1+ (1,0) [0|255] ""  PC
 SG_ D2P_Cfg2_SW_Ver_Byte13_59 : 40|8@1+ (1,0) [0|255] ""  PC
 SG_ D2P_Cfg2_SW_Ver_Byte14_59 : 48|8@1+ (1,0) [0|255] ""  PC
 SG_ D2P_Cfg2_SW_Ver_Byte15_59 : 56|8@1+ (1,0) [0|255] ""  PC

BO_ 2499931772 D2P_Cfg2__60: 8 DCDC
 SG_ D2P_Cfg2_SW_Ver_Byte8_60 : 0|8@1+ (1,0) [0|255] ""  PC
 SG_ D2P_Cfg2_SW_Ver_Byte9_60 : 8|8@1+ (1,0) [0|255] ""  PC
 SG_ D2P_Cfg2_SW_Ver_Byte10_60 : 16|8@1+ (1,0) [0|255] ""  PC
 SG_ D2P_Cfg2_SW_Ver_Byte11_60 : 24|8@1+ (1,0) [0|255] ""  PC
 SG_ D2P_Cfg2_SW_Ver_Byte12_60 : 32|8@1+ (1,0) [0|255] ""  PC
 SG_ D2P_Cfg2_SW_Ver_Byte13_60 : 40|8@1+ (1,0) [0|255] ""  PC
 SG_ D2P_Cfg2_SW_Ver_Byte14_60 : 48|8@1+ (1,0) [0|255] ""  PC
 SG_ D2P_Cfg2_SW_Ver_Byte15_60 : 56|8@1+ (1,0) [0|255] ""  PC

BO_ 2499931773 D2P_Cfg2__61: 8 DCDC
 SG_ D2P_Cfg2_SW_Ver_Byte8_61 : 0|8@1+ (1,0) [0|255] ""  PC
 SG_ D2P_Cfg2_SW_Ver_Byte9_61 : 8|8@1+ (1,0) [0|255] ""  PC
 SG_ D2P_Cfg2_SW_Ver_Byte10_61 : 16|8@1+ (1,0) [0|255] ""  PC
 SG_ D2P_Cfg2_SW_Ver_Byte11_61 : 24|8@1+ (1,0) [0|255] ""  PC
 SG_ D2P_Cfg2_SW_Ver_Byte12_61 : 32|8@1+ (1,0) [0|255] ""  PC
 SG_ D2P_Cfg2_SW_Ver_Byte13_61 : 40|8@1+ (1,0) [0|255] ""  PC
 SG_ D2P_Cfg2_SW_Ver_Byte14_61 : 48|8@1+ (1,0) [0|255] ""  PC
 SG_ D2P_Cfg2_SW_Ver_Byte15_61 : 56|8@1+ (1,0) [0|255] ""  PC

BO_ 2499931774 D2P_Cfg2__62: 8 DCDC
 SG_ D2P_Cfg2_SW_Ver_Byte8_62 : 0|8@1+ (1,0) [0|255] ""  PC
 SG_ D2P_Cfg2_SW_Ver_Byte9_62 : 8|8@1+ (1,0) [0|255] ""  PC
 SG_ D2P_Cfg2_SW_Ver_Byte10_62 : 16|8@1+ (1,0) [0|255] ""  PC
 SG_ D2P_Cfg2_SW_Ver_Byte11_62 : 24|8@1+ (1,0) [0|255] ""  PC
 SG_ D2P_Cfg2_SW_Ver_Byte12_62 : 32|8@1+ (1,0) [0|255] ""  PC
 SG_ D2P_Cfg2_SW_Ver_Byte13_62 : 40|8@1+ (1,0) [0|255] ""  PC
 SG_ D2P_Cfg2_SW_Ver_Byte14_62 : 48|8@1+ (1,0) [0|255] ""  PC
 SG_ D2P_Cfg2_SW_Ver_Byte15_62 : 56|8@1+ (1,0) [0|255] ""  PC

BO_ 2499931775 D2P_Cfg2__63: 8 DCDC
 SG_ D2P_Cfg2_SW_Ver_Byte8_63 : 0|8@1+ (1,0) [0|255] ""  PC
 SG_ D2P_Cfg2_SW_Ver_Byte9_63 : 8|8@1+ (1,0) [0|255] ""  PC
 SG_ D2P_Cfg2_SW_Ver_Byte10_63 : 16|8@1+ (1,0) [0|255] ""  PC
 SG_ D2P_Cfg2_SW_Ver_Byte11_63 : 24|8@1+ (1,0) [0|255] ""  PC
 SG_ D2P_Cfg2_SW_Ver_Byte12_63 : 32|8@1+ (1,0) [0|255] ""  PC
 SG_ D2P_Cfg2_SW_Ver_Byte13_63 : 40|8@1+ (1,0) [0|255] ""  PC
 SG_ D2P_Cfg2_SW_Ver_Byte14_63 : 48|8@1+ (1,0) [0|255] ""  PC
 SG_ D2P_Cfg2_SW_Ver_Byte15_63 : 56|8@1+ (1,0) [0|255] ""  PC

BO_ 2499997249 D2P_Cfg3__01: 8 DCDC
 SG_ D2P_Cfg3_HW_Ver_Byte0_01 : 0|8@1+ (1,0) [0|255] ""  PC
 SG_ D2P_Cfg3_HW_Ver_Byte1_01 : 8|8@1+ (1,0) [0|255] ""  PC
 SG_ D2P_Cfg3_HW_Ver_Byte2_01 : 16|8@1+ (1,0) [0|255] ""  PC
 SG_ D2P_Cfg3_HW_Ver_Byte3_01 : 24|8@1+ (1,0) [0|255] ""  PC
 SG_ D2P_Cfg3_HW_Ver_Byte4_01 : 32|8@1+ (1,0) [0|255] ""  PC
 SG_ D2P_Cfg3_HW_Ver_Byte5_01 : 40|8@1+ (1,0) [0|255] ""  PC
 SG_ D2P_Cfg3_HW_Ver_Byte6_01 : 48|8@1+ (1,0) [0|255] ""  PC
 SG_ D2P_Cfg3_HW_Ver_Byte7_01 : 56|8@1+ (1,0) [0|255] ""  PC

BO_ 2499997250 D2P_Cfg3__02: 8 DCDC
 SG_ D2P_Cfg3_HW_Ver_Byte0_02 : 0|8@1+ (1,0) [0|255] ""  PC
 SG_ D2P_Cfg3_HW_Ver_Byte1_02 : 8|8@1+ (1,0) [0|255] ""  PC
 SG_ D2P_Cfg3_HW_Ver_Byte2_02 : 16|8@1+ (1,0) [0|255] ""  PC
 SG_ D2P_Cfg3_HW_Ver_Byte3_02 : 24|8@1+ (1,0) [0|255] ""  PC
 SG_ D2P_Cfg3_HW_Ver_Byte4_02 : 32|8@1+ (1,0) [0|255] ""  PC
 SG_ D2P_Cfg3_HW_Ver_Byte5_02 : 40|8@1+ (1,0) [0|255] ""  PC
 SG_ D2P_Cfg3_HW_Ver_Byte6_02 : 48|8@1+ (1,0) [0|255] ""  PC
 SG_ D2P_Cfg3_HW_Ver_Byte7_02 : 56|8@1+ (1,0) [0|255] ""  PC

BO_ 2499997251 D2P_Cfg3__03: 8 DCDC
 SG_ D2P_Cfg3_HW_Ver_Byte0_03 : 0|8@1+ (1,0) [0|255] ""  PC
 SG_ D2P_Cfg3_HW_Ver_Byte1_03 : 8|8@1+ (1,0) [0|255] ""  PC
 SG_ D2P_Cfg3_HW_Ver_Byte2_03 : 16|8@1+ (1,0) [0|255] ""  PC
 SG_ D2P_Cfg3_HW_Ver_Byte3_03 : 24|8@1+ (1,0) [0|255] ""  PC
 SG_ D2P_Cfg3_HW_Ver_Byte4_03 : 32|8@1+ (1,0) [0|255] ""  PC
 SG_ D2P_Cfg3_HW_Ver_Byte5_03 : 40|8@1+ (1,0) [0|255] ""  PC
 SG_ D2P_Cfg3_HW_Ver_Byte6_03 : 48|8@1+ (1,0) [0|255] ""  PC
 SG_ D2P_Cfg3_HW_Ver_Byte7_03 : 56|8@1+ (1,0) [0|255] ""  PC

BO_ 2499997252 D2P_Cfg3__04: 8 DCDC
 SG_ D2P_Cfg3_HW_Ver_Byte0_04 : 0|8@1+ (1,0) [0|255] ""  PC
 SG_ D2P_Cfg3_HW_Ver_Byte1_04 : 8|8@1+ (1,0) [0|255] ""  PC
 SG_ D2P_Cfg3_HW_Ver_Byte2_04 : 16|8@1+ (1,0) [0|255] ""  PC
 SG_ D2P_Cfg3_HW_Ver_Byte3_04 : 24|8@1+ (1,0) [0|255] ""  PC
 SG_ D2P_Cfg3_HW_Ver_Byte4_04 : 32|8@1+ (1,0) [0|255] ""  PC
 SG_ D2P_Cfg3_HW_Ver_Byte5_04 : 40|8@1+ (1,0) [0|255] ""  PC
 SG_ D2P_Cfg3_HW_Ver_Byte6_04 : 48|8@1+ (1,0) [0|255] ""  PC
 SG_ D2P_Cfg3_HW_Ver_Byte7_04 : 56|8@1+ (1,0) [0|255] ""  PC

BO_ 2499997253 D2P_Cfg3__05: 8 DCDC
 SG_ D2P_Cfg3_HW_Ver_Byte0_05 : 0|8@1+ (1,0) [0|255] ""  PC
 SG_ D2P_Cfg3_HW_Ver_Byte1_05 : 8|8@1+ (1,0) [0|255] ""  PC
 SG_ D2P_Cfg3_HW_Ver_Byte2_05 : 16|8@1+ (1,0) [0|255] ""  PC
 SG_ D2P_Cfg3_HW_Ver_Byte3_05 : 24|8@1+ (1,0) [0|255] ""  PC
 SG_ D2P_Cfg3_HW_Ver_Byte4_05 : 32|8@1+ (1,0) [0|255] ""  PC
 SG_ D2P_Cfg3_HW_Ver_Byte5_05 : 40|8@1+ (1,0) [0|255] ""  PC
 SG_ D2P_Cfg3_HW_Ver_Byte6_05 : 48|8@1+ (1,0) [0|255] ""  PC
 SG_ D2P_Cfg3_HW_Ver_Byte7_05 : 56|8@1+ (1,0) [0|255] ""  PC

BO_ 2499997254 D2P_Cfg3__06: 8 DCDC
 SG_ D2P_Cfg3_HW_Ver_Byte0_06 : 0|8@1+ (1,0) [0|255] ""  PC
 SG_ D2P_Cfg3_HW_Ver_Byte1_06 : 8|8@1+ (1,0) [0|255] ""  PC
 SG_ D2P_Cfg3_HW_Ver_Byte2_06 : 16|8@1+ (1,0) [0|255] ""  PC
 SG_ D2P_Cfg3_HW_Ver_Byte3_06 : 24|8@1+ (1,0) [0|255] ""  PC
 SG_ D2P_Cfg3_HW_Ver_Byte4_06 : 32|8@1+ (1,0) [0|255] ""  PC
 SG_ D2P_Cfg3_HW_Ver_Byte5_06 : 40|8@1+ (1,0) [0|255] ""  PC
 SG_ D2P_Cfg3_HW_Ver_Byte6_06 : 48|8@1+ (1,0) [0|255] ""  PC
 SG_ D2P_Cfg3_HW_Ver_Byte7_06 : 56|8@1+ (1,0) [0|255] ""  PC

BO_ 2499997255 D2P_Cfg3__07: 8 DCDC
 SG_ D2P_Cfg3_HW_Ver_Byte0_07 : 0|8@1+ (1,0) [0|255] ""  PC
 SG_ D2P_Cfg3_HW_Ver_Byte1_07 : 8|8@1+ (1,0) [0|255] ""  PC
 SG_ D2P_Cfg3_HW_Ver_Byte2_07 : 16|8@1+ (1,0) [0|255] ""  PC
 SG_ D2P_Cfg3_HW_Ver_Byte3_07 : 24|8@1+ (1,0) [0|255] ""  PC
 SG_ D2P_Cfg3_HW_Ver_Byte4_07 : 32|8@1+ (1,0) [0|255] ""  PC
 SG_ D2P_Cfg3_HW_Ver_Byte5_07 : 40|8@1+ (1,0) [0|255] ""  PC
 SG_ D2P_Cfg3_HW_Ver_Byte6_07 : 48|8@1+ (1,0) [0|255] ""  PC
 SG_ D2P_Cfg3_HW_Ver_Byte7_07 : 56|8@1+ (1,0) [0|255] ""  PC

BO_ 2499997256 D2P_Cfg3__08: 8 DCDC
 SG_ D2P_Cfg3_HW_Ver_Byte0_08 : 0|8@1+ (1,0) [0|255] ""  PC
 SG_ D2P_Cfg3_HW_Ver_Byte1_08 : 8|8@1+ (1,0) [0|255] ""  PC
 SG_ D2P_Cfg3_HW_Ver_Byte2_08 : 16|8@1+ (1,0) [0|255] ""  PC
 SG_ D2P_Cfg3_HW_Ver_Byte3_08 : 24|8@1+ (1,0) [0|255] ""  PC
 SG_ D2P_Cfg3_HW_Ver_Byte4_08 : 32|8@1+ (1,0) [0|255] ""  PC
 SG_ D2P_Cfg3_HW_Ver_Byte5_08 : 40|8@1+ (1,0) [0|255] ""  PC
 SG_ D2P_Cfg3_HW_Ver_Byte6_08 : 48|8@1+ (1,0) [0|255] ""  PC
 SG_ D2P_Cfg3_HW_Ver_Byte7_08 : 56|8@1+ (1,0) [0|255] ""  PC

BO_ 2499997257 D2P_Cfg3__09: 8 DCDC
 SG_ D2P_Cfg3_HW_Ver_Byte0_09 : 0|8@1+ (1,0) [0|255] ""  PC
 SG_ D2P_Cfg3_HW_Ver_Byte1_09 : 8|8@1+ (1,0) [0|255] ""  PC
 SG_ D2P_Cfg3_HW_Ver_Byte2_09 : 16|8@1+ (1,0) [0|255] ""  PC
 SG_ D2P_Cfg3_HW_Ver_Byte3_09 : 24|8@1+ (1,0) [0|255] ""  PC
 SG_ D2P_Cfg3_HW_Ver_Byte4_09 : 32|8@1+ (1,0) [0|255] ""  PC
 SG_ D2P_Cfg3_HW_Ver_Byte5_09 : 40|8@1+ (1,0) [0|255] ""  PC
 SG_ D2P_Cfg3_HW_Ver_Byte6_09 : 48|8@1+ (1,0) [0|255] ""  PC
 SG_ D2P_Cfg3_HW_Ver_Byte7_09 : 56|8@1+ (1,0) [0|255] ""  PC

CM_ SG_ 2149285721 P2D_PrgData_Data0 "发送的flash数据报文字节0";
CM_ SG_ 2149285721 P2D_PrgData_Data1 "发送的flash数据报文字节1";
CM_ SG_ 2149285721 P2D_PrgData_Data2 "发送的flash数据报文字节2";
CM_ SG_ 2149285721 P2D_PrgData_Data3 "发送的flash数据报文字节3";
CM_ SG_ 2149285721 P2D_PrgData_Data4 "发送的flash数据报文字节4";
CM_ SG_ 2149285721 P2D_PrgData_Data5 "发送的flash数据报文字节5";
CM_ SG_ 2149285721 P2D_PrgData_Data6 "发送的flash数据报文字节6";
CM_ SG_ 2149285721 P2D_PrgData_Data7 "发送的flash数据报文字节7";
CM_ SG_ 2149285722 P2D_PrgData_Data0 "发送的flash数据报文字节0";
CM_ SG_ 2149285722 P2D_PrgData_Data1 "发送的flash数据报文字节1";
CM_ SG_ 2149285722 P2D_PrgData_Data2 "发送的flash数据报文字节2";
CM_ SG_ 2149285722 P2D_PrgData_Data3 "发送的flash数据报文字节3";
CM_ SG_ 2149285722 P2D_PrgData_Data4 "发送的flash数据报文字节4";
CM_ SG_ 2149285722 P2D_PrgData_Data5 "发送的flash数据报文字节5";
CM_ SG_ 2149285722 P2D_PrgData_Data6 "发送的flash数据报文字节6";
CM_ SG_ 2149285722 P2D_PrgData_Data7 "发送的flash数据报文字节7";
CM_ SG_ 2149285723 P2D_PrgData_Data0 "发送的flash数据报文字节0";
CM_ SG_ 2149285723 P2D_PrgData_Data1 "发送的flash数据报文字节1";
CM_ SG_ 2149285723 P2D_PrgData_Data2 "发送的flash数据报文字节2";
CM_ SG_ 2149285723 P2D_PrgData_Data3 "发送的flash数据报文字节3";
CM_ SG_ 2149285723 P2D_PrgData_Data4 "发送的flash数据报文字节4";
CM_ SG_ 2149285723 P2D_PrgData_Data5 "发送的flash数据报文字节5";
CM_ SG_ 2149285723 P2D_PrgData_Data6 "发送的flash数据报文字节6";
CM_ SG_ 2149285723 P2D_PrgData_Data7 "发送的flash数据报文字节7";
CM_ SG_ 2149285724 P2D_PrgData_Data0 "发送的flash数据报文字节0";
CM_ SG_ 2149285724 P2D_PrgData_Data1 "发送的flash数据报文字节1";
CM_ SG_ 2149285724 P2D_PrgData_Data2 "发送的flash数据报文字节2";
CM_ SG_ 2149285724 P2D_PrgData_Data3 "发送的flash数据报文字节3";
CM_ SG_ 2149285724 P2D_PrgData_Data4 "发送的flash数据报文字节4";
CM_ SG_ 2149285724 P2D_PrgData_Data5 "发送的flash数据报文字节5";
CM_ SG_ 2149285724 P2D_PrgData_Data6 "发送的flash数据报文字节6";
CM_ SG_ 2149285724 P2D_PrgData_Data7 "发送的flash数据报文字节7";
CM_ SG_ 2149285725 P2D_PrgData_Data0 "发送的flash数据报文字节0";
CM_ SG_ 2149285725 P2D_PrgData_Data1 "发送的flash数据报文字节1";
CM_ SG_ 2149285725 P2D_PrgData_Data2 "发送的flash数据报文字节2";
CM_ SG_ 2149285725 P2D_PrgData_Data3 "发送的flash数据报文字节3";
CM_ SG_ 2149285725 P2D_PrgData_Data4 "发送的flash数据报文字节4";
CM_ SG_ 2149285725 P2D_PrgData_Data5 "发送的flash数据报文字节5";
CM_ SG_ 2149285725 P2D_PrgData_Data6 "发送的flash数据报文字节6";
CM_ SG_ 2149285725 P2D_PrgData_Data7 "发送的flash数据报文字节7";
CM_ SG_ 2149285726 P2D_PrgData_Data0 "发送的flash数据报文字节0";
CM_ SG_ 2149285726 P2D_PrgData_Data1 "发送的flash数据报文字节1";
CM_ SG_ 2149285726 P2D_PrgData_Data2 "发送的flash数据报文字节2";
CM_ SG_ 2149285726 P2D_PrgData_Data3 "发送的flash数据报文字节3";
CM_ SG_ 2149285726 P2D_PrgData_Data4 "发送的flash数据报文字节4";
CM_ SG_ 2149285726 P2D_PrgData_Data5 "发送的flash数据报文字节5";
CM_ SG_ 2149285726 P2D_PrgData_Data6 "发送的flash数据报文字节6";
CM_ SG_ 2149285726 P2D_PrgData_Data7 "发送的flash数据报文字节7";
CM_ SG_ 2149285727 P2D_PrgData_Data0 "发送的flash数据报文字节0";
CM_ SG_ 2149285727 P2D_PrgData_Data1 "发送的flash数据报文字节1";
CM_ SG_ 2149285727 P2D_PrgData_Data2 "发送的flash数据报文字节2";
CM_ SG_ 2149285727 P2D_PrgData_Data3 "发送的flash数据报文字节3";
CM_ SG_ 2149285727 P2D_PrgData_Data4 "发送的flash数据报文字节4";
CM_ SG_ 2149285727 P2D_PrgData_Data5 "发送的flash数据报文字节5";
CM_ SG_ 2149285727 P2D_PrgData_Data6 "发送的flash数据报文字节6";
CM_ SG_ 2149285727 P2D_PrgData_Data7 "发送的flash数据报文字节7";
CM_ SG_ 2149285728 P2D_PrgData_Data0 "发送的flash数据报文字节0";
CM_ SG_ 2149285728 P2D_PrgData_Data1 "发送的flash数据报文字节1";
CM_ SG_ 2149285728 P2D_PrgData_Data2 "发送的flash数据报文字节2";
CM_ SG_ 2149285728 P2D_PrgData_Data3 "发送的flash数据报文字节3";
CM_ SG_ 2149285728 P2D_PrgData_Data4 "发送的flash数据报文字节4";
CM_ SG_ 2149285728 P2D_PrgData_Data5 "发送的flash数据报文字节5";
CM_ SG_ 2149285728 P2D_PrgData_Data6 "发送的flash数据报文字节6";
CM_ SG_ 2149285728 P2D_PrgData_Data7 "发送的flash数据报文字节7";
CM_ SG_ 2149285729 P2D_PrgData_Data0 "发送的flash数据报文字节0";
CM_ SG_ 2149285729 P2D_PrgData_Data1 "发送的flash数据报文字节1";
CM_ SG_ 2149285729 P2D_PrgData_Data2 "发送的flash数据报文字节2";
CM_ SG_ 2149285729 P2D_PrgData_Data3 "发送的flash数据报文字节3";
CM_ SG_ 2149285729 P2D_PrgData_Data4 "发送的flash数据报文字节4";
CM_ SG_ 2149285729 P2D_PrgData_Data5 "发送的flash数据报文字节5";
CM_ SG_ 2149285729 P2D_PrgData_Data6 "发送的flash数据报文字节6";
CM_ SG_ 2149285729 P2D_PrgData_Data7 "发送的flash数据报文字节7";
CM_ SG_ 2149285730 P2D_PrgData_Data0 "发送的flash数据报文字节0";
CM_ SG_ 2149285730 P2D_PrgData_Data1 "发送的flash数据报文字节1";
CM_ SG_ 2149285730 P2D_PrgData_Data2 "发送的flash数据报文字节2";
CM_ SG_ 2149285730 P2D_PrgData_Data3 "发送的flash数据报文字节3";
CM_ SG_ 2149285730 P2D_PrgData_Data4 "发送的flash数据报文字节4";
CM_ SG_ 2149285730 P2D_PrgData_Data5 "发送的flash数据报文字节5";
CM_ SG_ 2149285730 P2D_PrgData_Data6 "发送的flash数据报文字节6";
CM_ SG_ 2149285730 P2D_PrgData_Data7 "发送的flash数据报文字节7";
CM_ SG_ 2149285731 P2D_PrgData_Data0 "发送的flash数据报文字节0";
CM_ SG_ 2149285731 P2D_PrgData_Data1 "发送的flash数据报文字节1";
CM_ SG_ 2149285731 P2D_PrgData_Data2 "发送的flash数据报文字节2";
CM_ SG_ 2149285731 P2D_PrgData_Data3 "发送的flash数据报文字节3";
CM_ SG_ 2149285731 P2D_PrgData_Data4 "发送的flash数据报文字节4";
CM_ SG_ 2149285731 P2D_PrgData_Data5 "发送的flash数据报文字节5";
CM_ SG_ 2149285731 P2D_PrgData_Data6 "发送的flash数据报文字节6";
CM_ SG_ 2149285731 P2D_PrgData_Data7 "发送的flash数据报文字节7";
CM_ SG_ 2149285732 P2D_PrgData_Data0 "发送的flash数据报文字节0";
CM_ SG_ 2149285732 P2D_PrgData_Data1 "发送的flash数据报文字节1";
CM_ SG_ 2149285732 P2D_PrgData_Data2 "发送的flash数据报文字节2";
CM_ SG_ 2149285732 P2D_PrgData_Data3 "发送的flash数据报文字节3";
CM_ SG_ 2149285732 P2D_PrgData_Data4 "发送的flash数据报文字节4";
CM_ SG_ 2149285732 P2D_PrgData_Data5 "发送的flash数据报文字节5";
CM_ SG_ 2149285732 P2D_PrgData_Data6 "发送的flash数据报文字节6";
CM_ SG_ 2149285732 P2D_PrgData_Data7 "发送的flash数据报文字节7";
CM_ SG_ 2149285733 P2D_PrgData_Data0 "发送的flash数据报文字节0";
CM_ SG_ 2149285733 P2D_PrgData_Data1 "发送的flash数据报文字节1";
CM_ SG_ 2149285733 P2D_PrgData_Data2 "发送的flash数据报文字节2";
CM_ SG_ 2149285733 P2D_PrgData_Data3 "发送的flash数据报文字节3";
CM_ SG_ 2149285733 P2D_PrgData_Data4 "发送的flash数据报文字节4";
CM_ SG_ 2149285733 P2D_PrgData_Data5 "发送的flash数据报文字节5";
CM_ SG_ 2149285733 P2D_PrgData_Data6 "发送的flash数据报文字节6";
CM_ SG_ 2149285733 P2D_PrgData_Data7 "发送的flash数据报文字节7";
CM_ SG_ 2149285734 P2D_PrgData_Data0 "发送的flash数据报文字节0";
CM_ SG_ 2149285734 P2D_PrgData_Data1 "发送的flash数据报文字节1";
CM_ SG_ 2149285734 P2D_PrgData_Data2 "发送的flash数据报文字节2";
CM_ SG_ 2149285734 P2D_PrgData_Data3 "发送的flash数据报文字节3";
CM_ SG_ 2149285734 P2D_PrgData_Data4 "发送的flash数据报文字节4";
CM_ SG_ 2149285734 P2D_PrgData_Data5 "发送的flash数据报文字节5";
CM_ SG_ 2149285734 P2D_PrgData_Data6 "发送的flash数据报文字节6";
CM_ SG_ 2149285734 P2D_PrgData_Data7 "发送的flash数据报文字节7";
CM_ SG_ 2149285735 P2D_PrgData_Data0 "发送的flash数据报文字节0";
CM_ SG_ 2149285735 P2D_PrgData_Data1 "发送的flash数据报文字节1";
CM_ SG_ 2149285735 P2D_PrgData_Data2 "发送的flash数据报文字节2";
CM_ SG_ 2149285735 P2D_PrgData_Data3 "发送的flash数据报文字节3";
CM_ SG_ 2149285735 P2D_PrgData_Data4 "发送的flash数据报文字节4";
CM_ SG_ 2149285735 P2D_PrgData_Data5 "发送的flash数据报文字节5";
CM_ SG_ 2149285735 P2D_PrgData_Data6 "发送的flash数据报文字节6";
CM_ SG_ 2149285735 P2D_PrgData_Data7 "发送的flash数据报文字节7";
CM_ SG_ 2149285736 P2D_PrgData_Data0 "发送的flash数据报文字节0";
CM_ SG_ 2149285736 P2D_PrgData_Data1 "发送的flash数据报文字节1";
CM_ SG_ 2149285736 P2D_PrgData_Data2 "发送的flash数据报文字节2";
CM_ SG_ 2149285736 P2D_PrgData_Data3 "发送的flash数据报文字节3";
CM_ SG_ 2149285736 P2D_PrgData_Data4 "发送的flash数据报文字节4";
CM_ SG_ 2149285736 P2D_PrgData_Data5 "发送的flash数据报文字节5";
CM_ SG_ 2149285736 P2D_PrgData_Data6 "发送的flash数据报文字节6";
CM_ SG_ 2149285736 P2D_PrgData_Data7 "发送的flash数据报文字节7";
CM_ SG_ 2149285737 P2D_PrgData_Data0 "发送的flash数据报文字节0";
CM_ SG_ 2149285737 P2D_PrgData_Data1 "发送的flash数据报文字节1";
CM_ SG_ 2149285737 P2D_PrgData_Data2 "发送的flash数据报文字节2";
CM_ SG_ 2149285737 P2D_PrgData_Data3 "发送的flash数据报文字节3";
CM_ SG_ 2149285737 P2D_PrgData_Data4 "发送的flash数据报文字节4";
CM_ SG_ 2149285737 P2D_PrgData_Data5 "发送的flash数据报文字节5";
CM_ SG_ 2149285737 P2D_PrgData_Data6 "发送的flash数据报文字节6";
CM_ SG_ 2149285737 P2D_PrgData_Data7 "发送的flash数据报文字节7";
CM_ SG_ 2149285738 P2D_PrgData_Data0 "发送的flash数据报文字节0";
CM_ SG_ 2149285738 P2D_PrgData_Data1 "发送的flash数据报文字节1";
CM_ SG_ 2149285738 P2D_PrgData_Data2 "发送的flash数据报文字节2";
CM_ SG_ 2149285738 P2D_PrgData_Data3 "发送的flash数据报文字节3";
CM_ SG_ 2149285738 P2D_PrgData_Data4 "发送的flash数据报文字节4";
CM_ SG_ 2149285738 P2D_PrgData_Data5 "发送的flash数据报文字节5";
CM_ SG_ 2149285738 P2D_PrgData_Data6 "发送的flash数据报文字节6";
CM_ SG_ 2149285738 P2D_PrgData_Data7 "发送的flash数据报文字节7";
CM_ SG_ 2149285739 P2D_PrgData_Data0 "发送的flash数据报文字节0";
CM_ SG_ 2149285739 P2D_PrgData_Data1 "发送的flash数据报文字节1";
CM_ SG_ 2149285739 P2D_PrgData_Data2 "发送的flash数据报文字节2";
CM_ SG_ 2149285739 P2D_PrgData_Data3 "发送的flash数据报文字节3";
CM_ SG_ 2149285739 P2D_PrgData_Data4 "发送的flash数据报文字节4";
CM_ SG_ 2149285739 P2D_PrgData_Data5 "发送的flash数据报文字节5";
CM_ SG_ 2149285739 P2D_PrgData_Data6 "发送的flash数据报文字节6";
CM_ SG_ 2149285739 P2D_PrgData_Data7 "发送的flash数据报文字节7";
CM_ SG_ 2149285740 P2D_PrgData_Data0 "发送的flash数据报文字节0";
CM_ SG_ 2149285740 P2D_PrgData_Data1 "发送的flash数据报文字节1";
CM_ SG_ 2149285740 P2D_PrgData_Data2 "发送的flash数据报文字节2";
CM_ SG_ 2149285740 P2D_PrgData_Data3 "发送的flash数据报文字节3";
CM_ SG_ 2149285740 P2D_PrgData_Data4 "发送的flash数据报文字节4";
CM_ SG_ 2149285740 P2D_PrgData_Data5 "发送的flash数据报文字节5";
CM_ SG_ 2149285740 P2D_PrgData_Data6 "发送的flash数据报文字节6";
CM_ SG_ 2149285740 P2D_PrgData_Data7 "发送的flash数据报文字节7";
CM_ SG_ 2149285741 P2D_PrgData_Data0 "发送的flash数据报文字节0";
CM_ SG_ 2149285741 P2D_PrgData_Data1 "发送的flash数据报文字节1";
CM_ SG_ 2149285741 P2D_PrgData_Data2 "发送的flash数据报文字节2";
CM_ SG_ 2149285741 P2D_PrgData_Data3 "发送的flash数据报文字节3";
CM_ SG_ 2149285741 P2D_PrgData_Data4 "发送的flash数据报文字节4";
CM_ SG_ 2149285741 P2D_PrgData_Data5 "发送的flash数据报文字节5";
CM_ SG_ 2149285741 P2D_PrgData_Data6 "发送的flash数据报文字节6";
CM_ SG_ 2149285741 P2D_PrgData_Data7 "发送的flash数据报文字节7";
CM_ SG_ 2149285742 P2D_PrgData_Data0 "发送的flash数据报文字节0";
CM_ SG_ 2149285742 P2D_PrgData_Data1 "发送的flash数据报文字节1";
CM_ SG_ 2149285742 P2D_PrgData_Data2 "发送的flash数据报文字节2";
CM_ SG_ 2149285742 P2D_PrgData_Data3 "发送的flash数据报文字节3";
CM_ SG_ 2149285742 P2D_PrgData_Data4 "发送的flash数据报文字节4";
CM_ SG_ 2149285742 P2D_PrgData_Data5 "发送的flash数据报文字节5";
CM_ SG_ 2149285742 P2D_PrgData_Data6 "发送的flash数据报文字节6";
CM_ SG_ 2149285742 P2D_PrgData_Data7 "发送的flash数据报文字节7";
CM_ SG_ 2149285743 P2D_PrgData_Data0 "发送的flash数据报文字节0";
CM_ SG_ 2149285743 P2D_PrgData_Data1 "发送的flash数据报文字节1";
CM_ SG_ 2149285743 P2D_PrgData_Data2 "发送的flash数据报文字节2";
CM_ SG_ 2149285743 P2D_PrgData_Data3 "发送的flash数据报文字节3";
CM_ SG_ 2149285743 P2D_PrgData_Data4 "发送的flash数据报文字节4";
CM_ SG_ 2149285743 P2D_PrgData_Data5 "发送的flash数据报文字节5";
CM_ SG_ 2149285743 P2D_PrgData_Data6 "发送的flash数据报文字节6";
CM_ SG_ 2149285743 P2D_PrgData_Data7 "发送的flash数据报文字节7";
CM_ SG_ 2149285744 P2D_PrgData_Data0 "发送的flash数据报文字节0";
CM_ SG_ 2149285744 P2D_PrgData_Data1 "发送的flash数据报文字节1";
CM_ SG_ 2149285744 P2D_PrgData_Data2 "发送的flash数据报文字节2";
CM_ SG_ 2149285744 P2D_PrgData_Data3 "发送的flash数据报文字节3";
CM_ SG_ 2149285744 P2D_PrgData_Data4 "发送的flash数据报文字节4";
CM_ SG_ 2149285744 P2D_PrgData_Data5 "发送的flash数据报文字节5";
CM_ SG_ 2149285744 P2D_PrgData_Data6 "发送的flash数据报文字节6";
CM_ SG_ 2149285744 P2D_PrgData_Data7 "发送的flash数据报文字节7";
CM_ SG_ 2149285745 P2D_PrgData_Data0 "发送的flash数据报文字节0";
CM_ SG_ 2149285745 P2D_PrgData_Data1 "发送的flash数据报文字节1";
CM_ SG_ 2149285745 P2D_PrgData_Data2 "发送的flash数据报文字节2";
CM_ SG_ 2149285745 P2D_PrgData_Data3 "发送的flash数据报文字节3";
CM_ SG_ 2149285745 P2D_PrgData_Data4 "发送的flash数据报文字节4";
CM_ SG_ 2149285745 P2D_PrgData_Data5 "发送的flash数据报文字节5";
CM_ SG_ 2149285745 P2D_PrgData_Data6 "发送的flash数据报文字节6";
CM_ SG_ 2149285745 P2D_PrgData_Data7 "发送的flash数据报文字节7";
CM_ SG_ 2149285746 P2D_PrgData_Data0 "发送的flash数据报文字节0";
CM_ SG_ 2149285746 P2D_PrgData_Data1 "发送的flash数据报文字节1";
CM_ SG_ 2149285746 P2D_PrgData_Data2 "发送的flash数据报文字节2";
CM_ SG_ 2149285746 P2D_PrgData_Data3 "发送的flash数据报文字节3";
CM_ SG_ 2149285746 P2D_PrgData_Data4 "发送的flash数据报文字节4";
CM_ SG_ 2149285746 P2D_PrgData_Data5 "发送的flash数据报文字节5";
CM_ SG_ 2149285746 P2D_PrgData_Data6 "发送的flash数据报文字节6";
CM_ SG_ 2149285746 P2D_PrgData_Data7 "发送的flash数据报文字节7";
CM_ SG_ 2149285747 P2D_PrgData_Data0 "发送的flash数据报文字节0";
CM_ SG_ 2149285747 P2D_PrgData_Data1 "发送的flash数据报文字节1";
CM_ SG_ 2149285747 P2D_PrgData_Data2 "发送的flash数据报文字节2";
CM_ SG_ 2149285747 P2D_PrgData_Data3 "发送的flash数据报文字节3";
CM_ SG_ 2149285747 P2D_PrgData_Data4 "发送的flash数据报文字节4";
CM_ SG_ 2149285747 P2D_PrgData_Data5 "发送的flash数据报文字节5";
CM_ SG_ 2149285747 P2D_PrgData_Data6 "发送的flash数据报文字节6";
CM_ SG_ 2149285747 P2D_PrgData_Data7 "发送的flash数据报文字节7";
CM_ SG_ 2149285748 P2D_PrgData_Data0 "发送的flash数据报文字节0";
CM_ SG_ 2149285748 P2D_PrgData_Data1 "发送的flash数据报文字节1";
CM_ SG_ 2149285748 P2D_PrgData_Data2 "发送的flash数据报文字节2";
CM_ SG_ 2149285748 P2D_PrgData_Data3 "发送的flash数据报文字节3";
CM_ SG_ 2149285748 P2D_PrgData_Data4 "发送的flash数据报文字节4";
CM_ SG_ 2149285748 P2D_PrgData_Data5 "发送的flash数据报文字节5";
CM_ SG_ 2149285748 P2D_PrgData_Data6 "发送的flash数据报文字节6";
CM_ SG_ 2149285748 P2D_PrgData_Data7 "发送的flash数据报文字节7";
CM_ SG_ 2149285749 P2D_PrgData_Data0 "发送的flash数据报文字节0";
CM_ SG_ 2149285749 P2D_PrgData_Data1 "发送的flash数据报文字节1";
CM_ SG_ 2149285749 P2D_PrgData_Data2 "发送的flash数据报文字节2";
CM_ SG_ 2149285749 P2D_PrgData_Data3 "发送的flash数据报文字节3";
CM_ SG_ 2149285749 P2D_PrgData_Data4 "发送的flash数据报文字节4";
CM_ SG_ 2149285749 P2D_PrgData_Data5 "发送的flash数据报文字节5";
CM_ SG_ 2149285749 P2D_PrgData_Data6 "发送的flash数据报文字节6";
CM_ SG_ 2149285749 P2D_PrgData_Data7 "发送的flash数据报文字节7";
CM_ SG_ 2149285750 P2D_PrgData_Data0 "发送的flash数据报文字节0";
CM_ SG_ 2149285750 P2D_PrgData_Data1 "发送的flash数据报文字节1";
CM_ SG_ 2149285750 P2D_PrgData_Data2 "发送的flash数据报文字节2";
CM_ SG_ 2149285750 P2D_PrgData_Data3 "发送的flash数据报文字节3";
CM_ SG_ 2149285750 P2D_PrgData_Data4 "发送的flash数据报文字节4";
CM_ SG_ 2149285750 P2D_PrgData_Data5 "发送的flash数据报文字节5";
CM_ SG_ 2149285750 P2D_PrgData_Data6 "发送的flash数据报文字节6";
CM_ SG_ 2149285750 P2D_PrgData_Data7 "发送的flash数据报文字节7";
CM_ SG_ 2149285751 P2D_PrgData_Data0 "发送的flash数据报文字节0";
CM_ SG_ 2149285751 P2D_PrgData_Data1 "发送的flash数据报文字节1";
CM_ SG_ 2149285751 P2D_PrgData_Data2 "发送的flash数据报文字节2";
CM_ SG_ 2149285751 P2D_PrgData_Data3 "发送的flash数据报文字节3";
CM_ SG_ 2149285751 P2D_PrgData_Data4 "发送的flash数据报文字节4";
CM_ SG_ 2149285751 P2D_PrgData_Data5 "发送的flash数据报文字节5";
CM_ SG_ 2149285751 P2D_PrgData_Data6 "发送的flash数据报文字节6";
CM_ SG_ 2149285751 P2D_PrgData_Data7 "发送的flash数据报文字节7";
CM_ SG_ 2149285752 P2D_PrgData_Data0 "发送的flash数据报文字节0";
CM_ SG_ 2149285752 P2D_PrgData_Data1 "发送的flash数据报文字节1";
CM_ SG_ 2149285752 P2D_PrgData_Data2 "发送的flash数据报文字节2";
CM_ SG_ 2149285752 P2D_PrgData_Data3 "发送的flash数据报文字节3";
CM_ SG_ 2149285752 P2D_PrgData_Data4 "发送的flash数据报文字节4";
CM_ SG_ 2149285752 P2D_PrgData_Data5 "发送的flash数据报文字节5";
CM_ SG_ 2149285752 P2D_PrgData_Data6 "发送的flash数据报文字节6";
CM_ SG_ 2149285752 P2D_PrgData_Data7 "发送的flash数据报文字节7";
CM_ SG_ 2149285753 P2D_PrgData_Data0 "发送的flash数据报文字节0";
CM_ SG_ 2149285753 P2D_PrgData_Data1 "发送的flash数据报文字节1";
CM_ SG_ 2149285753 P2D_PrgData_Data2 "发送的flash数据报文字节2";
CM_ SG_ 2149285753 P2D_PrgData_Data3 "发送的flash数据报文字节3";
CM_ SG_ 2149285753 P2D_PrgData_Data4 "发送的flash数据报文字节4";
CM_ SG_ 2149285753 P2D_PrgData_Data5 "发送的flash数据报文字节5";
CM_ SG_ 2149285753 P2D_PrgData_Data6 "发送的flash数据报文字节6";
CM_ SG_ 2149285753 P2D_PrgData_Data7 "发送的flash数据报文字节7";
CM_ SG_ 2149285754 P2D_PrgData_Data0 "发送的flash数据报文字节0";
CM_ SG_ 2149285754 P2D_PrgData_Data1 "发送的flash数据报文字节1";
CM_ SG_ 2149285754 P2D_PrgData_Data2 "发送的flash数据报文字节2";
CM_ SG_ 2149285754 P2D_PrgData_Data3 "发送的flash数据报文字节3";
CM_ SG_ 2149285754 P2D_PrgData_Data4 "发送的flash数据报文字节4";
CM_ SG_ 2149285754 P2D_PrgData_Data5 "发送的flash数据报文字节5";
CM_ SG_ 2149285754 P2D_PrgData_Data6 "发送的flash数据报文字节6";
CM_ SG_ 2149285754 P2D_PrgData_Data7 "发送的flash数据报文字节7";
CM_ SG_ 2149285755 P2D_PrgData_Data0 "发送的flash数据报文字节0";
CM_ SG_ 2149285755 P2D_PrgData_Data1 "发送的flash数据报文字节1";
CM_ SG_ 2149285755 P2D_PrgData_Data2 "发送的flash数据报文字节2";
CM_ SG_ 2149285755 P2D_PrgData_Data3 "发送的flash数据报文字节3";
CM_ SG_ 2149285755 P2D_PrgData_Data4 "发送的flash数据报文字节4";
CM_ SG_ 2149285755 P2D_PrgData_Data5 "发送的flash数据报文字节5";
CM_ SG_ 2149285755 P2D_PrgData_Data6 "发送的flash数据报文字节6";
CM_ SG_ 2149285755 P2D_PrgData_Data7 "发送的flash数据报文字节7";
CM_ SG_ 2149285756 P2D_PrgData_Data0 "发送的flash数据报文字节0";
CM_ SG_ 2149285756 P2D_PrgData_Data1 "发送的flash数据报文字节1";
CM_ SG_ 2149285756 P2D_PrgData_Data2 "发送的flash数据报文字节2";
CM_ SG_ 2149285756 P2D_PrgData_Data3 "发送的flash数据报文字节3";
CM_ SG_ 2149285756 P2D_PrgData_Data4 "发送的flash数据报文字节4";
CM_ SG_ 2149285756 P2D_PrgData_Data5 "发送的flash数据报文字节5";
CM_ SG_ 2149285756 P2D_PrgData_Data6 "发送的flash数据报文字节6";
CM_ SG_ 2149285756 P2D_PrgData_Data7 "发送的flash数据报文字节7";
CM_ SG_ 2149285757 P2D_PrgData_Data0 "发送的flash数据报文字节0";
CM_ SG_ 2149285757 P2D_PrgData_Data1 "发送的flash数据报文字节1";
CM_ SG_ 2149285757 P2D_PrgData_Data2 "发送的flash数据报文字节2";
CM_ SG_ 2149285757 P2D_PrgData_Data3 "发送的flash数据报文字节3";
CM_ SG_ 2149285757 P2D_PrgData_Data4 "发送的flash数据报文字节4";
CM_ SG_ 2149285757 P2D_PrgData_Data5 "发送的flash数据报文字节5";
CM_ SG_ 2149285757 P2D_PrgData_Data6 "发送的flash数据报文字节6";
CM_ SG_ 2149285757 P2D_PrgData_Data7 "发送的flash数据报文字节7";
CM_ SG_ 2149285758 P2D_PrgData_Data0 "发送的flash数据报文字节0";
CM_ SG_ 2149285758 P2D_PrgData_Data1 "发送的flash数据报文字节1";
CM_ SG_ 2149285758 P2D_PrgData_Data2 "发送的flash数据报文字节2";
CM_ SG_ 2149285758 P2D_PrgData_Data3 "发送的flash数据报文字节3";
CM_ SG_ 2149285758 P2D_PrgData_Data4 "发送的flash数据报文字节4";
CM_ SG_ 2149285758 P2D_PrgData_Data5 "发送的flash数据报文字节5";
CM_ SG_ 2149285758 P2D_PrgData_Data6 "发送的flash数据报文字节6";
CM_ SG_ 2149285758 P2D_PrgData_Data7 "发送的flash数据报文字节7";
CM_ SG_ 2149285759 P2D_PrgData_Data0 "发送的flash数据报文字节0";
CM_ SG_ 2149285759 P2D_PrgData_Data1 "发送的flash数据报文字节1";
CM_ SG_ 2149285759 P2D_PrgData_Data2 "发送的flash数据报文字节2";
CM_ SG_ 2149285759 P2D_PrgData_Data3 "发送的flash数据报文字节3";
CM_ SG_ 2149285759 P2D_PrgData_Data4 "发送的flash数据报文字节4";
CM_ SG_ 2149285759 P2D_PrgData_Data5 "发送的flash数据报文字节5";
CM_ SG_ 2149285759 P2D_PrgData_Data6 "发送的flash数据报文字节6";
CM_ SG_ 2149285759 P2D_PrgData_Data7 "发送的flash数据报文字节7";
CM_ SG_ 2499866177 D2P_Cfg1_SW_Ver_Byte0_01 "DCDC软件版本号最低字节Byte0对应ASCII码";
CM_ SG_ 2499866177 D2P_Cfg1_SW_Ver_Byte1_01 "DCDC软件版本号Byte1对应ASCII码";
CM_ SG_ 2499866177 D2P_Cfg1_SW_Ver_Byte2_01 "DCDC软件版本号Byte2对应ASCII码";
CM_ SG_ 2499866177 D2P_Cfg1_SW_Ver_Byte3_01 "DCDC软件版本号Byte3对应ASCII码";
CM_ SG_ 2499866177 D2P_Cfg1_SW_Ver_Byte4_01 "DCDC软件版本号Byte4对应ASCII码";
CM_ SG_ 2499866177 D2P_Cfg1_SW_Ver_Byte5_01 "DCDC软件版本号Byte5对应ASCII码";
CM_ SG_ 2499866177 D2P_Cfg1_SW_Ver_Byte6_01 "DCDC软件版本号Byte6对应ASCII码";
CM_ SG_ 2499866177 D2P_Cfg1_SW_Ver_Byte7_01 "DCDC软件版本号Byte7对应ASCII码";
CM_ SG_ 2499866178 D2P_Cfg1_SW_Ver_Byte0_02 "DCDC软件版本号最低字节Byte0对应ASCII码";
CM_ SG_ 2499866178 D2P_Cfg1_SW_Ver_Byte1_02 "DCDC软件版本号Byte1对应ASCII码";
CM_ SG_ 2499866178 D2P_Cfg1_SW_Ver_Byte2_02 "DCDC软件版本号Byte2对应ASCII码";
CM_ SG_ 2499866178 D2P_Cfg1_SW_Ver_Byte3_02 "DCDC软件版本号Byte3对应ASCII码";
CM_ SG_ 2499866178 D2P_Cfg1_SW_Ver_Byte4_02 "DCDC软件版本号Byte4对应ASCII码";
CM_ SG_ 2499866178 D2P_Cfg1_SW_Ver_Byte5_02 "DCDC软件版本号Byte5对应ASCII码";
CM_ SG_ 2499866178 D2P_Cfg1_SW_Ver_Byte6_02 "DCDC软件版本号Byte6对应ASCII码";
CM_ SG_ 2499866178 D2P_Cfg1_SW_Ver_Byte7_02 "DCDC软件版本号Byte7对应ASCII码";
CM_ SG_ 2499866179 D2P_Cfg1_SW_Ver_Byte0_03 "DCDC软件版本号最低字节Byte0对应ASCII码";
CM_ SG_ 2499866179 D2P_Cfg1_SW_Ver_Byte1_03 "DCDC软件版本号Byte1对应ASCII码";
CM_ SG_ 2499866179 D2P_Cfg1_SW_Ver_Byte2_03 "DCDC软件版本号Byte2对应ASCII码";
CM_ SG_ 2499866179 D2P_Cfg1_SW_Ver_Byte3_03 "DCDC软件版本号Byte3对应ASCII码";
CM_ SG_ 2499866179 D2P_Cfg1_SW_Ver_Byte4_03 "DCDC软件版本号Byte4对应ASCII码";
CM_ SG_ 2499866179 D2P_Cfg1_SW_Ver_Byte5_03 "DCDC软件版本号Byte5对应ASCII码";
CM_ SG_ 2499866179 D2P_Cfg1_SW_Ver_Byte6_03 "DCDC软件版本号Byte6对应ASCII码";
CM_ SG_ 2499866179 D2P_Cfg1_SW_Ver_Byte7_03 "DCDC软件版本号Byte7对应ASCII码";
CM_ SG_ 2499866180 D2P_Cfg1_SW_Ver_Byte0_04 "DCDC软件版本号最低字节Byte0对应ASCII码";
CM_ SG_ 2499866180 D2P_Cfg1_SW_Ver_Byte1_04 "DCDC软件版本号Byte1对应ASCII码";
CM_ SG_ 2499866180 D2P_Cfg1_SW_Ver_Byte2_04 "DCDC软件版本号Byte2对应ASCII码";
CM_ SG_ 2499866180 D2P_Cfg1_SW_Ver_Byte3_04 "DCDC软件版本号Byte3对应ASCII码";
CM_ SG_ 2499866180 D2P_Cfg1_SW_Ver_Byte4_04 "DCDC软件版本号Byte4对应ASCII码";
CM_ SG_ 2499866180 D2P_Cfg1_SW_Ver_Byte5_04 "DCDC软件版本号Byte5对应ASCII码";
CM_ SG_ 2499866180 D2P_Cfg1_SW_Ver_Byte6_04 "DCDC软件版本号Byte6对应ASCII码";
CM_ SG_ 2499866180 D2P_Cfg1_SW_Ver_Byte7_04 "DCDC软件版本号Byte7对应ASCII码";
CM_ SG_ 2499866181 D2P_Cfg1_SW_Ver_Byte0_05 "DCDC软件版本号最低字节Byte0对应ASCII码";
CM_ SG_ 2499866181 D2P_Cfg1_SW_Ver_Byte1_05 "DCDC软件版本号Byte1对应ASCII码";
CM_ SG_ 2499866181 D2P_Cfg1_SW_Ver_Byte2_05 "DCDC软件版本号Byte2对应ASCII码";
CM_ SG_ 2499866181 D2P_Cfg1_SW_Ver_Byte3_05 "DCDC软件版本号Byte3对应ASCII码";
CM_ SG_ 2499866181 D2P_Cfg1_SW_Ver_Byte4_05 "DCDC软件版本号Byte4对应ASCII码";
CM_ SG_ 2499866181 D2P_Cfg1_SW_Ver_Byte5_05 "DCDC软件版本号Byte5对应ASCII码";
CM_ SG_ 2499866181 D2P_Cfg1_SW_Ver_Byte6_05 "DCDC软件版本号Byte6对应ASCII码";
CM_ SG_ 2499866181 D2P_Cfg1_SW_Ver_Byte7_05 "DCDC软件版本号Byte7对应ASCII码";
CM_ SG_ 2499866182 D2P_Cfg1_SW_Ver_Byte0_06 "DCDC软件版本号最低字节Byte0对应ASCII码";
CM_ SG_ 2499866182 D2P_Cfg1_SW_Ver_Byte1_06 "DCDC软件版本号Byte1对应ASCII码";
CM_ SG_ 2499866182 D2P_Cfg1_SW_Ver_Byte2_06 "DCDC软件版本号Byte2对应ASCII码";
CM_ SG_ 2499866182 D2P_Cfg1_SW_Ver_Byte3_06 "DCDC软件版本号Byte3对应ASCII码";
CM_ SG_ 2499866182 D2P_Cfg1_SW_Ver_Byte4_06 "DCDC软件版本号Byte4对应ASCII码";
CM_ SG_ 2499866182 D2P_Cfg1_SW_Ver_Byte5_06 "DCDC软件版本号Byte5对应ASCII码";
CM_ SG_ 2499866182 D2P_Cfg1_SW_Ver_Byte6_06 "DCDC软件版本号Byte6对应ASCII码";
CM_ SG_ 2499866182 D2P_Cfg1_SW_Ver_Byte7_06 "DCDC软件版本号Byte7对应ASCII码";
CM_ SG_ 2499866183 D2P_Cfg1_SW_Ver_Byte0_07 "DCDC软件版本号最低字节Byte0对应ASCII码";
CM_ SG_ 2499866183 D2P_Cfg1_SW_Ver_Byte1_07 "DCDC软件版本号Byte1对应ASCII码";
CM_ SG_ 2499866183 D2P_Cfg1_SW_Ver_Byte2_07 "DCDC软件版本号Byte2对应ASCII码";
CM_ SG_ 2499866183 D2P_Cfg1_SW_Ver_Byte3_07 "DCDC软件版本号Byte3对应ASCII码";
CM_ SG_ 2499866183 D2P_Cfg1_SW_Ver_Byte4_07 "DCDC软件版本号Byte4对应ASCII码";
CM_ SG_ 2499866183 D2P_Cfg1_SW_Ver_Byte5_07 "DCDC软件版本号Byte5对应ASCII码";
CM_ SG_ 2499866183 D2P_Cfg1_SW_Ver_Byte6_07 "DCDC软件版本号Byte6对应ASCII码";
CM_ SG_ 2499866183 D2P_Cfg1_SW_Ver_Byte7_07 "DCDC软件版本号Byte7对应ASCII码";
CM_ SG_ 2499866184 D2P_Cfg1_SW_Ver_Byte0_08 "DCDC软件版本号最低字节Byte0对应ASCII码";
CM_ SG_ 2499866184 D2P_Cfg1_SW_Ver_Byte1_08 "DCDC软件版本号Byte1对应ASCII码";
CM_ SG_ 2499866184 D2P_Cfg1_SW_Ver_Byte2_08 "DCDC软件版本号Byte2对应ASCII码";
CM_ SG_ 2499866184 D2P_Cfg1_SW_Ver_Byte3_08 "DCDC软件版本号Byte3对应ASCII码";
CM_ SG_ 2499866184 D2P_Cfg1_SW_Ver_Byte4_08 "DCDC软件版本号Byte4对应ASCII码";
CM_ SG_ 2499866184 D2P_Cfg1_SW_Ver_Byte5_08 "DCDC软件版本号Byte5对应ASCII码";
CM_ SG_ 2499866184 D2P_Cfg1_SW_Ver_Byte6_08 "DCDC软件版本号Byte6对应ASCII码";
CM_ SG_ 2499866184 D2P_Cfg1_SW_Ver_Byte7_08 "DCDC软件版本号Byte7对应ASCII码";
CM_ SG_ 2499866185 D2P_Cfg1_SW_Ver_Byte0_09 "DCDC软件版本号最低字节Byte0对应ASCII码";
CM_ SG_ 2499866185 D2P_Cfg1_SW_Ver_Byte1_09 "DCDC软件版本号Byte1对应ASCII码";
CM_ SG_ 2499866185 D2P_Cfg1_SW_Ver_Byte2_09 "DCDC软件版本号Byte2对应ASCII码";
CM_ SG_ 2499866185 D2P_Cfg1_SW_Ver_Byte3_09 "DCDC软件版本号Byte3对应ASCII码";
CM_ SG_ 2499866185 D2P_Cfg1_SW_Ver_Byte4_09 "DCDC软件版本号Byte4对应ASCII码";
CM_ SG_ 2499866185 D2P_Cfg1_SW_Ver_Byte5_09 "DCDC软件版本号Byte5对应ASCII码";
CM_ SG_ 2499866185 D2P_Cfg1_SW_Ver_Byte6_09 "DCDC软件版本号Byte6对应ASCII码";
CM_ SG_ 2499866185 D2P_Cfg1_SW_Ver_Byte7_09 "DCDC软件版本号Byte7对应ASCII码";
CM_ SG_ 2499866186 D2P_Cfg1_SW_Ver_Byte0_10 "DCDC软件版本号最低字节Byte0对应ASCII码";
CM_ SG_ 2499866186 D2P_Cfg1_SW_Ver_Byte1_10 "DCDC软件版本号Byte1对应ASCII码";
CM_ SG_ 2499866186 D2P_Cfg1_SW_Ver_Byte2_10 "DCDC软件版本号Byte2对应ASCII码";
CM_ SG_ 2499866186 D2P_Cfg1_SW_Ver_Byte3_10 "DCDC软件版本号Byte3对应ASCII码";
CM_ SG_ 2499866186 D2P_Cfg1_SW_Ver_Byte4_10 "DCDC软件版本号Byte4对应ASCII码";
CM_ SG_ 2499866186 D2P_Cfg1_SW_Ver_Byte5_10 "DCDC软件版本号Byte5对应ASCII码";
CM_ SG_ 2499866186 D2P_Cfg1_SW_Ver_Byte6_10 "DCDC软件版本号Byte6对应ASCII码";
CM_ SG_ 2499866186 D2P_Cfg1_SW_Ver_Byte7_10 "DCDC软件版本号Byte7对应ASCII码";
CM_ SG_ 2499866187 D2P_Cfg1_SW_Ver_Byte0_11 "DCDC软件版本号最低字节Byte0对应ASCII码";
CM_ SG_ 2499866187 D2P_Cfg1_SW_Ver_Byte1_11 "DCDC软件版本号Byte1对应ASCII码";
CM_ SG_ 2499866187 D2P_Cfg1_SW_Ver_Byte2_11 "DCDC软件版本号Byte2对应ASCII码";
CM_ SG_ 2499866187 D2P_Cfg1_SW_Ver_Byte3_11 "DCDC软件版本号Byte3对应ASCII码";
CM_ SG_ 2499866187 D2P_Cfg1_SW_Ver_Byte4_11 "DCDC软件版本号Byte4对应ASCII码";
CM_ SG_ 2499866187 D2P_Cfg1_SW_Ver_Byte5_11 "DCDC软件版本号Byte5对应ASCII码";
CM_ SG_ 2499866187 D2P_Cfg1_SW_Ver_Byte6_11 "DCDC软件版本号Byte6对应ASCII码";
CM_ SG_ 2499866187 D2P_Cfg1_SW_Ver_Byte7_11 "DCDC软件版本号Byte7对应ASCII码";
CM_ SG_ 2499866188 D2P_Cfg1_SW_Ver_Byte0_12 "DCDC软件版本号最低字节Byte0对应ASCII码";
CM_ SG_ 2499866188 D2P_Cfg1_SW_Ver_Byte1_12 "DCDC软件版本号Byte1对应ASCII码";
CM_ SG_ 2499866188 D2P_Cfg1_SW_Ver_Byte2_12 "DCDC软件版本号Byte2对应ASCII码";
CM_ SG_ 2499866188 D2P_Cfg1_SW_Ver_Byte3_12 "DCDC软件版本号Byte3对应ASCII码";
CM_ SG_ 2499866188 D2P_Cfg1_SW_Ver_Byte4_12 "DCDC软件版本号Byte4对应ASCII码";
CM_ SG_ 2499866188 D2P_Cfg1_SW_Ver_Byte5_12 "DCDC软件版本号Byte5对应ASCII码";
CM_ SG_ 2499866188 D2P_Cfg1_SW_Ver_Byte6_12 "DCDC软件版本号Byte6对应ASCII码";
CM_ SG_ 2499866188 D2P_Cfg1_SW_Ver_Byte7_12 "DCDC软件版本号Byte7对应ASCII码";
CM_ SG_ 2499866189 D2P_Cfg1_SW_Ver_Byte0_13 "DCDC软件版本号最低字节Byte0对应ASCII码";
CM_ SG_ 2499866189 D2P_Cfg1_SW_Ver_Byte1_13 "DCDC软件版本号Byte1对应ASCII码";
CM_ SG_ 2499866189 D2P_Cfg1_SW_Ver_Byte2_13 "DCDC软件版本号Byte2对应ASCII码";
CM_ SG_ 2499866189 D2P_Cfg1_SW_Ver_Byte3_13 "DCDC软件版本号Byte3对应ASCII码";
CM_ SG_ 2499866189 D2P_Cfg1_SW_Ver_Byte4_13 "DCDC软件版本号Byte4对应ASCII码";
CM_ SG_ 2499866189 D2P_Cfg1_SW_Ver_Byte5_13 "DCDC软件版本号Byte5对应ASCII码";
CM_ SG_ 2499866189 D2P_Cfg1_SW_Ver_Byte6_13 "DCDC软件版本号Byte6对应ASCII码";
CM_ SG_ 2499866189 D2P_Cfg1_SW_Ver_Byte7_13 "DCDC软件版本号Byte7对应ASCII码";
CM_ SG_ 2499866190 D2P_Cfg1_SW_Ver_Byte0_14 "DCDC软件版本号最低字节Byte0对应ASCII码";
CM_ SG_ 2499866190 D2P_Cfg1_SW_Ver_Byte1_14 "DCDC软件版本号Byte1对应ASCII码";
CM_ SG_ 2499866190 D2P_Cfg1_SW_Ver_Byte2_14 "DCDC软件版本号Byte2对应ASCII码";
CM_ SG_ 2499866190 D2P_Cfg1_SW_Ver_Byte3_14 "DCDC软件版本号Byte3对应ASCII码";
CM_ SG_ 2499866190 D2P_Cfg1_SW_Ver_Byte4_14 "DCDC软件版本号Byte4对应ASCII码";
CM_ SG_ 2499866190 D2P_Cfg1_SW_Ver_Byte5_14 "DCDC软件版本号Byte5对应ASCII码";
CM_ SG_ 2499866190 D2P_Cfg1_SW_Ver_Byte6_14 "DCDC软件版本号Byte6对应ASCII码";
CM_ SG_ 2499866190 D2P_Cfg1_SW_Ver_Byte7_14 "DCDC软件版本号Byte7对应ASCII码";
CM_ SG_ 2499866191 D2P_Cfg1_SW_Ver_Byte0_15 "DCDC软件版本号最低字节Byte0对应ASCII码";
CM_ SG_ 2499866191 D2P_Cfg1_SW_Ver_Byte1_15 "DCDC软件版本号Byte1对应ASCII码";
CM_ SG_ 2499866191 D2P_Cfg1_SW_Ver_Byte2_15 "DCDC软件版本号Byte2对应ASCII码";
CM_ SG_ 2499866191 D2P_Cfg1_SW_Ver_Byte3_15 "DCDC软件版本号Byte3对应ASCII码";
CM_ SG_ 2499866191 D2P_Cfg1_SW_Ver_Byte4_15 "DCDC软件版本号Byte4对应ASCII码";
CM_ SG_ 2499866191 D2P_Cfg1_SW_Ver_Byte5_15 "DCDC软件版本号Byte5对应ASCII码";
CM_ SG_ 2499866191 D2P_Cfg1_SW_Ver_Byte6_15 "DCDC软件版本号Byte6对应ASCII码";
CM_ SG_ 2499866191 D2P_Cfg1_SW_Ver_Byte7_15 "DCDC软件版本号Byte7对应ASCII码";
CM_ SG_ 2499866192 D2P_Cfg1_SW_Ver_Byte0_16 "DCDC软件版本号最低字节Byte0对应ASCII码";
CM_ SG_ 2499866192 D2P_Cfg1_SW_Ver_Byte1_16 "DCDC软件版本号Byte1对应ASCII码";
CM_ SG_ 2499866192 D2P_Cfg1_SW_Ver_Byte2_16 "DCDC软件版本号Byte2对应ASCII码";
CM_ SG_ 2499866192 D2P_Cfg1_SW_Ver_Byte3_16 "DCDC软件版本号Byte3对应ASCII码";
CM_ SG_ 2499866192 D2P_Cfg1_SW_Ver_Byte4_16 "DCDC软件版本号Byte4对应ASCII码";
CM_ SG_ 2499866192 D2P_Cfg1_SW_Ver_Byte5_16 "DCDC软件版本号Byte5对应ASCII码";
CM_ SG_ 2499866192 D2P_Cfg1_SW_Ver_Byte6_16 "DCDC软件版本号Byte6对应ASCII码";
CM_ SG_ 2499866192 D2P_Cfg1_SW_Ver_Byte7_16 "DCDC软件版本号Byte7对应ASCII码";
CM_ SG_ 2499866193 D2P_Cfg1_SW_Ver_Byte0_17 "DCDC软件版本号最低字节Byte0对应ASCII码";
CM_ SG_ 2499866193 D2P_Cfg1_SW_Ver_Byte1_17 "DCDC软件版本号Byte1对应ASCII码";
CM_ SG_ 2499866193 D2P_Cfg1_SW_Ver_Byte2_17 "DCDC软件版本号Byte2对应ASCII码";
CM_ SG_ 2499866193 D2P_Cfg1_SW_Ver_Byte3_17 "DCDC软件版本号Byte3对应ASCII码";
CM_ SG_ 2499866193 D2P_Cfg1_SW_Ver_Byte4_17 "DCDC软件版本号Byte4对应ASCII码";
CM_ SG_ 2499866193 D2P_Cfg1_SW_Ver_Byte5_17 "DCDC软件版本号Byte5对应ASCII码";
CM_ SG_ 2499866193 D2P_Cfg1_SW_Ver_Byte6_17 "DCDC软件版本号Byte6对应ASCII码";
CM_ SG_ 2499866193 D2P_Cfg1_SW_Ver_Byte7_17 "DCDC软件版本号Byte7对应ASCII码";
CM_ SG_ 2499866194 D2P_Cfg1_SW_Ver_Byte0_18 "DCDC软件版本号最低字节Byte0对应ASCII码";
CM_ SG_ 2499866194 D2P_Cfg1_SW_Ver_Byte1_18 "DCDC软件版本号Byte1对应ASCII码";
CM_ SG_ 2499866194 D2P_Cfg1_SW_Ver_Byte2_18 "DCDC软件版本号Byte2对应ASCII码";
CM_ SG_ 2499866194 D2P_Cfg1_SW_Ver_Byte3_18 "DCDC软件版本号Byte3对应ASCII码";
CM_ SG_ 2499866194 D2P_Cfg1_SW_Ver_Byte4_18 "DCDC软件版本号Byte4对应ASCII码";
CM_ SG_ 2499866194 D2P_Cfg1_SW_Ver_Byte5_18 "DCDC软件版本号Byte5对应ASCII码";
CM_ SG_ 2499866194 D2P_Cfg1_SW_Ver_Byte6_18 "DCDC软件版本号Byte6对应ASCII码";
CM_ SG_ 2499866194 D2P_Cfg1_SW_Ver_Byte7_18 "DCDC软件版本号Byte7对应ASCII码";
CM_ SG_ 2499866195 D2P_Cfg1_SW_Ver_Byte0_19 "DCDC软件版本号最低字节Byte0对应ASCII码";
CM_ SG_ 2499866195 D2P_Cfg1_SW_Ver_Byte1_19 "DCDC软件版本号Byte1对应ASCII码";
CM_ SG_ 2499866195 D2P_Cfg1_SW_Ver_Byte2_19 "DCDC软件版本号Byte2对应ASCII码";
CM_ SG_ 2499866195 D2P_Cfg1_SW_Ver_Byte3_19 "DCDC软件版本号Byte3对应ASCII码";
CM_ SG_ 2499866195 D2P_Cfg1_SW_Ver_Byte4_19 "DCDC软件版本号Byte4对应ASCII码";
CM_ SG_ 2499866195 D2P_Cfg1_SW_Ver_Byte5_19 "DCDC软件版本号Byte5对应ASCII码";
CM_ SG_ 2499866195 D2P_Cfg1_SW_Ver_Byte6_19 "DCDC软件版本号Byte6对应ASCII码";
CM_ SG_ 2499866195 D2P_Cfg1_SW_Ver_Byte7_19 "DCDC软件版本号Byte7对应ASCII码";
CM_ SG_ 2499866196 D2P_Cfg1_SW_Ver_Byte0_20 "DCDC软件版本号最低字节Byte0对应ASCII码";
CM_ SG_ 2499866196 D2P_Cfg1_SW_Ver_Byte1_20 "DCDC软件版本号Byte1对应ASCII码";
CM_ SG_ 2499866196 D2P_Cfg1_SW_Ver_Byte2_20 "DCDC软件版本号Byte2对应ASCII码";
CM_ SG_ 2499866196 D2P_Cfg1_SW_Ver_Byte3_20 "DCDC软件版本号Byte3对应ASCII码";
CM_ SG_ 2499866196 D2P_Cfg1_SW_Ver_Byte4_20 "DCDC软件版本号Byte4对应ASCII码";
CM_ SG_ 2499866196 D2P_Cfg1_SW_Ver_Byte5_20 "DCDC软件版本号Byte5对应ASCII码";
CM_ SG_ 2499866196 D2P_Cfg1_SW_Ver_Byte6_20 "DCDC软件版本号Byte6对应ASCII码";
CM_ SG_ 2499866196 D2P_Cfg1_SW_Ver_Byte7_20 "DCDC软件版本号Byte7对应ASCII码";
CM_ SG_ 2499866197 D2P_Cfg1_SW_Ver_Byte0_21 "DCDC软件版本号最低字节Byte0对应ASCII码";
CM_ SG_ 2499866197 D2P_Cfg1_SW_Ver_Byte1_21 "DCDC软件版本号Byte1对应ASCII码";
CM_ SG_ 2499866197 D2P_Cfg1_SW_Ver_Byte2_21 "DCDC软件版本号Byte2对应ASCII码";
CM_ SG_ 2499866197 D2P_Cfg1_SW_Ver_Byte3_21 "DCDC软件版本号Byte3对应ASCII码";
CM_ SG_ 2499866197 D2P_Cfg1_SW_Ver_Byte4_21 "DCDC软件版本号Byte4对应ASCII码";
CM_ SG_ 2499866197 D2P_Cfg1_SW_Ver_Byte5_21 "DCDC软件版本号Byte5对应ASCII码";
CM_ SG_ 2499866197 D2P_Cfg1_SW_Ver_Byte6_21 "DCDC软件版本号Byte6对应ASCII码";
CM_ SG_ 2499866197 D2P_Cfg1_SW_Ver_Byte7_21 "DCDC软件版本号Byte7对应ASCII码";
CM_ SG_ 2499866198 D2P_Cfg1_SW_Ver_Byte0_22 "DCDC软件版本号最低字节Byte0对应ASCII码";
CM_ SG_ 2499866198 D2P_Cfg1_SW_Ver_Byte1_22 "DCDC软件版本号Byte1对应ASCII码";
CM_ SG_ 2499866198 D2P_Cfg1_SW_Ver_Byte2_22 "DCDC软件版本号Byte2对应ASCII码";
CM_ SG_ 2499866198 D2P_Cfg1_SW_Ver_Byte3_22 "DCDC软件版本号Byte3对应ASCII码";
CM_ SG_ 2499866198 D2P_Cfg1_SW_Ver_Byte4_22 "DCDC软件版本号Byte4对应ASCII码";
CM_ SG_ 2499866198 D2P_Cfg1_SW_Ver_Byte5_22 "DCDC软件版本号Byte5对应ASCII码";
CM_ SG_ 2499866198 D2P_Cfg1_SW_Ver_Byte6_22 "DCDC软件版本号Byte6对应ASCII码";
CM_ SG_ 2499866198 D2P_Cfg1_SW_Ver_Byte7_22 "DCDC软件版本号Byte7对应ASCII码";
CM_ SG_ 2499866199 D2P_Cfg1_SW_Ver_Byte0_23 "DCDC软件版本号最低字节Byte0对应ASCII码";
CM_ SG_ 2499866199 D2P_Cfg1_SW_Ver_Byte1_23 "DCDC软件版本号Byte1对应ASCII码";
CM_ SG_ 2499866199 D2P_Cfg1_SW_Ver_Byte2_23 "DCDC软件版本号Byte2对应ASCII码";
CM_ SG_ 2499866199 D2P_Cfg1_SW_Ver_Byte3_23 "DCDC软件版本号Byte3对应ASCII码";
CM_ SG_ 2499866199 D2P_Cfg1_SW_Ver_Byte4_23 "DCDC软件版本号Byte4对应ASCII码";
CM_ SG_ 2499866199 D2P_Cfg1_SW_Ver_Byte5_23 "DCDC软件版本号Byte5对应ASCII码";
CM_ SG_ 2499866199 D2P_Cfg1_SW_Ver_Byte6_23 "DCDC软件版本号Byte6对应ASCII码";
CM_ SG_ 2499866199 D2P_Cfg1_SW_Ver_Byte7_23 "DCDC软件版本号Byte7对应ASCII码";
CM_ SG_ 2499866200 D2P_Cfg1_SW_Ver_Byte0_24 "DCDC软件版本号最低字节Byte0对应ASCII码";
CM_ SG_ 2499866200 D2P_Cfg1_SW_Ver_Byte1_24 "DCDC软件版本号Byte1对应ASCII码";
CM_ SG_ 2499866200 D2P_Cfg1_SW_Ver_Byte2_24 "DCDC软件版本号Byte2对应ASCII码";
CM_ SG_ 2499866200 D2P_Cfg1_SW_Ver_Byte3_24 "DCDC软件版本号Byte3对应ASCII码";
CM_ SG_ 2499866200 D2P_Cfg1_SW_Ver_Byte4_24 "DCDC软件版本号Byte4对应ASCII码";
CM_ SG_ 2499866200 D2P_Cfg1_SW_Ver_Byte5_24 "DCDC软件版本号Byte5对应ASCII码";
CM_ SG_ 2499866200 D2P_Cfg1_SW_Ver_Byte6_24 "DCDC软件版本号Byte6对应ASCII码";
CM_ SG_ 2499866200 D2P_Cfg1_SW_Ver_Byte7_24 "DCDC软件版本号Byte7对应ASCII码";
CM_ SG_ 2499866201 D2P_Cfg1_SW_Ver_Byte0_25 "DCDC软件版本号最低字节Byte0对应ASCII码";
CM_ SG_ 2499866201 D2P_Cfg1_SW_Ver_Byte1_25 "DCDC软件版本号Byte1对应ASCII码";
CM_ SG_ 2499866201 D2P_Cfg1_SW_Ver_Byte2_25 "DCDC软件版本号Byte2对应ASCII码";
CM_ SG_ 2499866201 D2P_Cfg1_SW_Ver_Byte3_25 "DCDC软件版本号Byte3对应ASCII码";
CM_ SG_ 2499866201 D2P_Cfg1_SW_Ver_Byte4_25 "DCDC软件版本号Byte4对应ASCII码";
CM_ SG_ 2499866201 D2P_Cfg1_SW_Ver_Byte5_25 "DCDC软件版本号Byte5对应ASCII码";
CM_ SG_ 2499866201 D2P_Cfg1_SW_Ver_Byte6_25 "DCDC软件版本号Byte6对应ASCII码";
CM_ SG_ 2499866201 D2P_Cfg1_SW_Ver_Byte7_25 "DCDC软件版本号Byte7对应ASCII码";
CM_ SG_ 2499866202 D2P_Cfg1_SW_Ver_Byte0_26 "DCDC软件版本号最低字节Byte0对应ASCII码";
CM_ SG_ 2499866202 D2P_Cfg1_SW_Ver_Byte1_26 "DCDC软件版本号Byte1对应ASCII码";
CM_ SG_ 2499866202 D2P_Cfg1_SW_Ver_Byte2_26 "DCDC软件版本号Byte2对应ASCII码";
CM_ SG_ 2499866202 D2P_Cfg1_SW_Ver_Byte3_26 "DCDC软件版本号Byte3对应ASCII码";
CM_ SG_ 2499866202 D2P_Cfg1_SW_Ver_Byte4_26 "DCDC软件版本号Byte4对应ASCII码";
CM_ SG_ 2499866202 D2P_Cfg1_SW_Ver_Byte5_26 "DCDC软件版本号Byte5对应ASCII码";
CM_ SG_ 2499866202 D2P_Cfg1_SW_Ver_Byte6_26 "DCDC软件版本号Byte6对应ASCII码";
CM_ SG_ 2499866202 D2P_Cfg1_SW_Ver_Byte7_26 "DCDC软件版本号Byte7对应ASCII码";
CM_ SG_ 2499866203 D2P_Cfg1_SW_Ver_Byte0_27 "DCDC软件版本号最低字节Byte0对应ASCII码";
CM_ SG_ 2499866203 D2P_Cfg1_SW_Ver_Byte1_27 "DCDC软件版本号Byte1对应ASCII码";
CM_ SG_ 2499866203 D2P_Cfg1_SW_Ver_Byte2_27 "DCDC软件版本号Byte2对应ASCII码";
CM_ SG_ 2499866203 D2P_Cfg1_SW_Ver_Byte3_27 "DCDC软件版本号Byte3对应ASCII码";
CM_ SG_ 2499866203 D2P_Cfg1_SW_Ver_Byte4_27 "DCDC软件版本号Byte4对应ASCII码";
CM_ SG_ 2499866203 D2P_Cfg1_SW_Ver_Byte5_27 "DCDC软件版本号Byte5对应ASCII码";
CM_ SG_ 2499866203 D2P_Cfg1_SW_Ver_Byte6_27 "DCDC软件版本号Byte6对应ASCII码";
CM_ SG_ 2499866203 D2P_Cfg1_SW_Ver_Byte7_27 "DCDC软件版本号Byte7对应ASCII码";
CM_ SG_ 2499866204 D2P_Cfg1_SW_Ver_Byte0_28 "DCDC软件版本号最低字节Byte0对应ASCII码";
CM_ SG_ 2499866204 D2P_Cfg1_SW_Ver_Byte1_28 "DCDC软件版本号Byte1对应ASCII码";
CM_ SG_ 2499866204 D2P_Cfg1_SW_Ver_Byte2_28 "DCDC软件版本号Byte2对应ASCII码";
CM_ SG_ 2499866204 D2P_Cfg1_SW_Ver_Byte3_28 "DCDC软件版本号Byte3对应ASCII码";
CM_ SG_ 2499866204 D2P_Cfg1_SW_Ver_Byte4_28 "DCDC软件版本号Byte4对应ASCII码";
CM_ SG_ 2499866204 D2P_Cfg1_SW_Ver_Byte5_28 "DCDC软件版本号Byte5对应ASCII码";
CM_ SG_ 2499866204 D2P_Cfg1_SW_Ver_Byte6_28 "DCDC软件版本号Byte6对应ASCII码";
CM_ SG_ 2499866204 D2P_Cfg1_SW_Ver_Byte7_28 "DCDC软件版本号Byte7对应ASCII码";
CM_ SG_ 2499866205 D2P_Cfg1_SW_Ver_Byte0_29 "DCDC软件版本号最低字节Byte0对应ASCII码";
CM_ SG_ 2499866205 D2P_Cfg1_SW_Ver_Byte1_29 "DCDC软件版本号Byte1对应ASCII码";
CM_ SG_ 2499866205 D2P_Cfg1_SW_Ver_Byte2_29 "DCDC软件版本号Byte2对应ASCII码";
CM_ SG_ 2499866205 D2P_Cfg1_SW_Ver_Byte3_29 "DCDC软件版本号Byte3对应ASCII码";
CM_ SG_ 2499866205 D2P_Cfg1_SW_Ver_Byte4_29 "DCDC软件版本号Byte4对应ASCII码";
CM_ SG_ 2499866205 D2P_Cfg1_SW_Ver_Byte5_29 "DCDC软件版本号Byte5对应ASCII码";
CM_ SG_ 2499866205 D2P_Cfg1_SW_Ver_Byte6_29 "DCDC软件版本号Byte6对应ASCII码";
CM_ SG_ 2499866205 D2P_Cfg1_SW_Ver_Byte7_29 "DCDC软件版本号Byte7对应ASCII码";
CM_ SG_ 2499866206 D2P_Cfg1_SW_Ver_Byte0_30 "DCDC软件版本号最低字节Byte0对应ASCII码";
CM_ SG_ 2499866206 D2P_Cfg1_SW_Ver_Byte1_30 "DCDC软件版本号Byte1对应ASCII码";
CM_ SG_ 2499866206 D2P_Cfg1_SW_Ver_Byte2_30 "DCDC软件版本号Byte2对应ASCII码";
CM_ SG_ 2499866206 D2P_Cfg1_SW_Ver_Byte3_30 "DCDC软件版本号Byte3对应ASCII码";
CM_ SG_ 2499866206 D2P_Cfg1_SW_Ver_Byte4_30 "DCDC软件版本号Byte4对应ASCII码";
CM_ SG_ 2499866206 D2P_Cfg1_SW_Ver_Byte5_30 "DCDC软件版本号Byte5对应ASCII码";
CM_ SG_ 2499866206 D2P_Cfg1_SW_Ver_Byte6_30 "DCDC软件版本号Byte6对应ASCII码";
CM_ SG_ 2499866206 D2P_Cfg1_SW_Ver_Byte7_30 "DCDC软件版本号Byte7对应ASCII码";
CM_ SG_ 2499866207 D2P_Cfg1_SW_Ver_Byte0_31 "DCDC软件版本号最低字节Byte0对应ASCII码";
CM_ SG_ 2499866207 D2P_Cfg1_SW_Ver_Byte1_31 "DCDC软件版本号Byte1对应ASCII码";
CM_ SG_ 2499866207 D2P_Cfg1_SW_Ver_Byte2_31 "DCDC软件版本号Byte2对应ASCII码";
CM_ SG_ 2499866207 D2P_Cfg1_SW_Ver_Byte3_31 "DCDC软件版本号Byte3对应ASCII码";
CM_ SG_ 2499866207 D2P_Cfg1_SW_Ver_Byte4_31 "DCDC软件版本号Byte4对应ASCII码";
CM_ SG_ 2499866207 D2P_Cfg1_SW_Ver_Byte5_31 "DCDC软件版本号Byte5对应ASCII码";
CM_ SG_ 2499866207 D2P_Cfg1_SW_Ver_Byte6_31 "DCDC软件版本号Byte6对应ASCII码";
CM_ SG_ 2499866207 D2P_Cfg1_SW_Ver_Byte7_31 "DCDC软件版本号Byte7对应ASCII码";
CM_ SG_ 2499866208 D2P_Cfg1_SW_Ver_Byte0_32 "DCDC软件版本号最低字节Byte0对应ASCII码";
CM_ SG_ 2499866208 D2P_Cfg1_SW_Ver_Byte1_32 "DCDC软件版本号Byte1对应ASCII码";
CM_ SG_ 2499866208 D2P_Cfg1_SW_Ver_Byte2_32 "DCDC软件版本号Byte2对应ASCII码";
CM_ SG_ 2499866208 D2P_Cfg1_SW_Ver_Byte3_32 "DCDC软件版本号Byte3对应ASCII码";
CM_ SG_ 2499866208 D2P_Cfg1_SW_Ver_Byte4_32 "DCDC软件版本号Byte4对应ASCII码";
CM_ SG_ 2499866208 D2P_Cfg1_SW_Ver_Byte5_32 "DCDC软件版本号Byte5对应ASCII码";
CM_ SG_ 2499866208 D2P_Cfg1_SW_Ver_Byte6_32 "DCDC软件版本号Byte6对应ASCII码";
CM_ SG_ 2499866208 D2P_Cfg1_SW_Ver_Byte7_32 "DCDC软件版本号Byte7对应ASCII码";
CM_ SG_ 2499866209 D2P_Cfg1_SW_Ver_Byte0_33 "DCDC软件版本号最低字节Byte0对应ASCII码";
CM_ SG_ 2499866209 D2P_Cfg1_SW_Ver_Byte1_33 "DCDC软件版本号Byte1对应ASCII码";
CM_ SG_ 2499866209 D2P_Cfg1_SW_Ver_Byte2_33 "DCDC软件版本号Byte2对应ASCII码";
CM_ SG_ 2499866209 D2P_Cfg1_SW_Ver_Byte3_33 "DCDC软件版本号Byte3对应ASCII码";
CM_ SG_ 2499866209 D2P_Cfg1_SW_Ver_Byte4_33 "DCDC软件版本号Byte4对应ASCII码";
CM_ SG_ 2499866209 D2P_Cfg1_SW_Ver_Byte5_33 "DCDC软件版本号Byte5对应ASCII码";
CM_ SG_ 2499866209 D2P_Cfg1_SW_Ver_Byte6_33 "DCDC软件版本号Byte6对应ASCII码";
CM_ SG_ 2499866209 D2P_Cfg1_SW_Ver_Byte7_33 "DCDC软件版本号Byte7对应ASCII码";
CM_ SG_ 2499866210 D2P_Cfg1_SW_Ver_Byte0_34 "DCDC软件版本号最低字节Byte0对应ASCII码";
CM_ SG_ 2499866210 D2P_Cfg1_SW_Ver_Byte1_34 "DCDC软件版本号Byte1对应ASCII码";
CM_ SG_ 2499866210 D2P_Cfg1_SW_Ver_Byte2_34 "DCDC软件版本号Byte2对应ASCII码";
CM_ SG_ 2499866210 D2P_Cfg1_SW_Ver_Byte3_34 "DCDC软件版本号Byte3对应ASCII码";
CM_ SG_ 2499866210 D2P_Cfg1_SW_Ver_Byte4_34 "DCDC软件版本号Byte4对应ASCII码";
CM_ SG_ 2499866210 D2P_Cfg1_SW_Ver_Byte5_34 "DCDC软件版本号Byte5对应ASCII码";
CM_ SG_ 2499866210 D2P_Cfg1_SW_Ver_Byte6_34 "DCDC软件版本号Byte6对应ASCII码";
CM_ SG_ 2499866210 D2P_Cfg1_SW_Ver_Byte7_34 "DCDC软件版本号Byte7对应ASCII码";
CM_ SG_ 2499866211 D2P_Cfg1_SW_Ver_Byte0_35 "DCDC软件版本号最低字节Byte0对应ASCII码";
CM_ SG_ 2499866211 D2P_Cfg1_SW_Ver_Byte1_35 "DCDC软件版本号Byte1对应ASCII码";
CM_ SG_ 2499866211 D2P_Cfg1_SW_Ver_Byte2_35 "DCDC软件版本号Byte2对应ASCII码";
CM_ SG_ 2499866211 D2P_Cfg1_SW_Ver_Byte3_35 "DCDC软件版本号Byte3对应ASCII码";
CM_ SG_ 2499866211 D2P_Cfg1_SW_Ver_Byte4_35 "DCDC软件版本号Byte4对应ASCII码";
CM_ SG_ 2499866211 D2P_Cfg1_SW_Ver_Byte5_35 "DCDC软件版本号Byte5对应ASCII码";
CM_ SG_ 2499866211 D2P_Cfg1_SW_Ver_Byte6_35 "DCDC软件版本号Byte6对应ASCII码";
CM_ SG_ 2499866211 D2P_Cfg1_SW_Ver_Byte7_35 "DCDC软件版本号Byte7对应ASCII码";
CM_ SG_ 2499866212 D2P_Cfg1_SW_Ver_Byte0_36 "DCDC软件版本号最低字节Byte0对应ASCII码";
CM_ SG_ 2499866212 D2P_Cfg1_SW_Ver_Byte1_36 "DCDC软件版本号Byte1对应ASCII码";
CM_ SG_ 2499866212 D2P_Cfg1_SW_Ver_Byte2_36 "DCDC软件版本号Byte2对应ASCII码";
CM_ SG_ 2499866212 D2P_Cfg1_SW_Ver_Byte3_36 "DCDC软件版本号Byte3对应ASCII码";
CM_ SG_ 2499866212 D2P_Cfg1_SW_Ver_Byte4_36 "DCDC软件版本号Byte4对应ASCII码";
CM_ SG_ 2499866212 D2P_Cfg1_SW_Ver_Byte5_36 "DCDC软件版本号Byte5对应ASCII码";
CM_ SG_ 2499866212 D2P_Cfg1_SW_Ver_Byte6_36 "DCDC软件版本号Byte6对应ASCII码";
CM_ SG_ 2499866212 D2P_Cfg1_SW_Ver_Byte7_36 "DCDC软件版本号Byte7对应ASCII码";
CM_ SG_ 2499866213 D2P_Cfg1_SW_Ver_Byte0_37 "DCDC软件版本号最低字节Byte0对应ASCII码";
CM_ SG_ 2499866213 D2P_Cfg1_SW_Ver_Byte1_37 "DCDC软件版本号Byte1对应ASCII码";
CM_ SG_ 2499866213 D2P_Cfg1_SW_Ver_Byte2_37 "DCDC软件版本号Byte2对应ASCII码";
CM_ SG_ 2499866213 D2P_Cfg1_SW_Ver_Byte3_37 "DCDC软件版本号Byte3对应ASCII码";
CM_ SG_ 2499866213 D2P_Cfg1_SW_Ver_Byte4_37 "DCDC软件版本号Byte4对应ASCII码";
CM_ SG_ 2499866213 D2P_Cfg1_SW_Ver_Byte5_37 "DCDC软件版本号Byte5对应ASCII码";
CM_ SG_ 2499866213 D2P_Cfg1_SW_Ver_Byte6_37 "DCDC软件版本号Byte6对应ASCII码";
CM_ SG_ 2499866213 D2P_Cfg1_SW_Ver_Byte7_37 "DCDC软件版本号Byte7对应ASCII码";
CM_ SG_ 2499866214 D2P_Cfg1_SW_Ver_Byte0_38 "DCDC软件版本号最低字节Byte0对应ASCII码";
CM_ SG_ 2499866214 D2P_Cfg1_SW_Ver_Byte1_38 "DCDC软件版本号Byte1对应ASCII码";
CM_ SG_ 2499866214 D2P_Cfg1_SW_Ver_Byte2_38 "DCDC软件版本号Byte2对应ASCII码";
CM_ SG_ 2499866214 D2P_Cfg1_SW_Ver_Byte3_38 "DCDC软件版本号Byte3对应ASCII码";
CM_ SG_ 2499866214 D2P_Cfg1_SW_Ver_Byte4_38 "DCDC软件版本号Byte4对应ASCII码";
CM_ SG_ 2499866214 D2P_Cfg1_SW_Ver_Byte5_38 "DCDC软件版本号Byte5对应ASCII码";
CM_ SG_ 2499866214 D2P_Cfg1_SW_Ver_Byte6_38 "DCDC软件版本号Byte6对应ASCII码";
CM_ SG_ 2499866214 D2P_Cfg1_SW_Ver_Byte7_38 "DCDC软件版本号Byte7对应ASCII码";
CM_ SG_ 2499866215 D2P_Cfg1_SW_Ver_Byte0_39 "DCDC软件版本号最低字节Byte0对应ASCII码";
CM_ SG_ 2499866215 D2P_Cfg1_SW_Ver_Byte1_39 "DCDC软件版本号Byte1对应ASCII码";
CM_ SG_ 2499866215 D2P_Cfg1_SW_Ver_Byte2_39 "DCDC软件版本号Byte2对应ASCII码";
CM_ SG_ 2499866215 D2P_Cfg1_SW_Ver_Byte3_39 "DCDC软件版本号Byte3对应ASCII码";
CM_ SG_ 2499866215 D2P_Cfg1_SW_Ver_Byte4_39 "DCDC软件版本号Byte4对应ASCII码";
CM_ SG_ 2499866215 D2P_Cfg1_SW_Ver_Byte5_39 "DCDC软件版本号Byte5对应ASCII码";
CM_ SG_ 2499866215 D2P_Cfg1_SW_Ver_Byte6_39 "DCDC软件版本号Byte6对应ASCII码";
CM_ SG_ 2499866215 D2P_Cfg1_SW_Ver_Byte7_39 "DCDC软件版本号Byte7对应ASCII码";
CM_ SG_ 2499866216 D2P_Cfg1_SW_Ver_Byte0_40 "DCDC软件版本号最低字节Byte0对应ASCII码";
CM_ SG_ 2499866216 D2P_Cfg1_SW_Ver_Byte1_40 "DCDC软件版本号Byte1对应ASCII码";
CM_ SG_ 2499866216 D2P_Cfg1_SW_Ver_Byte2_40 "DCDC软件版本号Byte2对应ASCII码";
CM_ SG_ 2499866216 D2P_Cfg1_SW_Ver_Byte3_40 "DCDC软件版本号Byte3对应ASCII码";
CM_ SG_ 2499866216 D2P_Cfg1_SW_Ver_Byte4_40 "DCDC软件版本号Byte4对应ASCII码";
CM_ SG_ 2499866216 D2P_Cfg1_SW_Ver_Byte5_40 "DCDC软件版本号Byte5对应ASCII码";
CM_ SG_ 2499866216 D2P_Cfg1_SW_Ver_Byte6_40 "DCDC软件版本号Byte6对应ASCII码";
CM_ SG_ 2499866216 D2P_Cfg1_SW_Ver_Byte7_40 "DCDC软件版本号Byte7对应ASCII码";
CM_ SG_ 2499866217 D2P_Cfg1_SW_Ver_Byte0_41 "DCDC软件版本号最低字节Byte0对应ASCII码";
CM_ SG_ 2499866217 D2P_Cfg1_SW_Ver_Byte1_41 "DCDC软件版本号Byte1对应ASCII码";
CM_ SG_ 2499866217 D2P_Cfg1_SW_Ver_Byte2_41 "DCDC软件版本号Byte2对应ASCII码";
CM_ SG_ 2499866217 D2P_Cfg1_SW_Ver_Byte3_41 "DCDC软件版本号Byte3对应ASCII码";
CM_ SG_ 2499866217 D2P_Cfg1_SW_Ver_Byte4_41 "DCDC软件版本号Byte4对应ASCII码";
CM_ SG_ 2499866217 D2P_Cfg1_SW_Ver_Byte5_41 "DCDC软件版本号Byte5对应ASCII码";
CM_ SG_ 2499866217 D2P_Cfg1_SW_Ver_Byte6_41 "DCDC软件版本号Byte6对应ASCII码";
CM_ SG_ 2499866217 D2P_Cfg1_SW_Ver_Byte7_41 "DCDC软件版本号Byte7对应ASCII码";
CM_ SG_ 2499866218 D2P_Cfg1_SW_Ver_Byte0_42 "DCDC软件版本号最低字节Byte0对应ASCII码";
CM_ SG_ 2499866218 D2P_Cfg1_SW_Ver_Byte1_42 "DCDC软件版本号Byte1对应ASCII码";
CM_ SG_ 2499866218 D2P_Cfg1_SW_Ver_Byte2_42 "DCDC软件版本号Byte2对应ASCII码";
CM_ SG_ 2499866218 D2P_Cfg1_SW_Ver_Byte3_42 "DCDC软件版本号Byte3对应ASCII码";
CM_ SG_ 2499866218 D2P_Cfg1_SW_Ver_Byte4_42 "DCDC软件版本号Byte4对应ASCII码";
CM_ SG_ 2499866218 D2P_Cfg1_SW_Ver_Byte5_42 "DCDC软件版本号Byte5对应ASCII码";
CM_ SG_ 2499866218 D2P_Cfg1_SW_Ver_Byte6_42 "DCDC软件版本号Byte6对应ASCII码";
CM_ SG_ 2499866218 D2P_Cfg1_SW_Ver_Byte7_42 "DCDC软件版本号Byte7对应ASCII码";
CM_ SG_ 2499866219 D2P_Cfg1_SW_Ver_Byte0_43 "DCDC软件版本号最低字节Byte0对应ASCII码";
CM_ SG_ 2499866219 D2P_Cfg1_SW_Ver_Byte1_43 "DCDC软件版本号Byte1对应ASCII码";
CM_ SG_ 2499866219 D2P_Cfg1_SW_Ver_Byte2_43 "DCDC软件版本号Byte2对应ASCII码";
CM_ SG_ 2499866219 D2P_Cfg1_SW_Ver_Byte3_43 "DCDC软件版本号Byte3对应ASCII码";
CM_ SG_ 2499866219 D2P_Cfg1_SW_Ver_Byte4_43 "DCDC软件版本号Byte4对应ASCII码";
CM_ SG_ 2499866219 D2P_Cfg1_SW_Ver_Byte5_43 "DCDC软件版本号Byte5对应ASCII码";
CM_ SG_ 2499866219 D2P_Cfg1_SW_Ver_Byte6_43 "DCDC软件版本号Byte6对应ASCII码";
CM_ SG_ 2499866219 D2P_Cfg1_SW_Ver_Byte7_43 "DCDC软件版本号Byte7对应ASCII码";
CM_ SG_ 2499866220 D2P_Cfg1_SW_Ver_Byte0_44 "DCDC软件版本号最低字节Byte0对应ASCII码";
CM_ SG_ 2499866220 D2P_Cfg1_SW_Ver_Byte1_44 "DCDC软件版本号Byte1对应ASCII码";
CM_ SG_ 2499866220 D2P_Cfg1_SW_Ver_Byte2_44 "DCDC软件版本号Byte2对应ASCII码";
CM_ SG_ 2499866220 D2P_Cfg1_SW_Ver_Byte3_44 "DCDC软件版本号Byte3对应ASCII码";
CM_ SG_ 2499866220 D2P_Cfg1_SW_Ver_Byte4_44 "DCDC软件版本号Byte4对应ASCII码";
CM_ SG_ 2499866220 D2P_Cfg1_SW_Ver_Byte5_44 "DCDC软件版本号Byte5对应ASCII码";
CM_ SG_ 2499866220 D2P_Cfg1_SW_Ver_Byte6_44 "DCDC软件版本号Byte6对应ASCII码";
CM_ SG_ 2499866220 D2P_Cfg1_SW_Ver_Byte7_44 "DCDC软件版本号Byte7对应ASCII码";
CM_ SG_ 2499866221 D2P_Cfg1_SW_Ver_Byte0_45 "DCDC软件版本号最低字节Byte0对应ASCII码";
CM_ SG_ 2499866221 D2P_Cfg1_SW_Ver_Byte1_45 "DCDC软件版本号Byte1对应ASCII码";
CM_ SG_ 2499866221 D2P_Cfg1_SW_Ver_Byte2_45 "DCDC软件版本号Byte2对应ASCII码";
CM_ SG_ 2499866221 D2P_Cfg1_SW_Ver_Byte3_45 "DCDC软件版本号Byte3对应ASCII码";
CM_ SG_ 2499866221 D2P_Cfg1_SW_Ver_Byte4_45 "DCDC软件版本号Byte4对应ASCII码";
CM_ SG_ 2499866221 D2P_Cfg1_SW_Ver_Byte5_45 "DCDC软件版本号Byte5对应ASCII码";
CM_ SG_ 2499866221 D2P_Cfg1_SW_Ver_Byte6_45 "DCDC软件版本号Byte6对应ASCII码";
CM_ SG_ 2499866221 D2P_Cfg1_SW_Ver_Byte7_45 "DCDC软件版本号Byte7对应ASCII码";
CM_ SG_ 2499866222 D2P_Cfg1_SW_Ver_Byte0_46 "DCDC软件版本号最低字节Byte0对应ASCII码";
CM_ SG_ 2499866222 D2P_Cfg1_SW_Ver_Byte1_46 "DCDC软件版本号Byte1对应ASCII码";
CM_ SG_ 2499866222 D2P_Cfg1_SW_Ver_Byte2_46 "DCDC软件版本号Byte2对应ASCII码";
CM_ SG_ 2499866222 D2P_Cfg1_SW_Ver_Byte3_46 "DCDC软件版本号Byte3对应ASCII码";
CM_ SG_ 2499866222 D2P_Cfg1_SW_Ver_Byte4_46 "DCDC软件版本号Byte4对应ASCII码";
CM_ SG_ 2499866222 D2P_Cfg1_SW_Ver_Byte5_46 "DCDC软件版本号Byte5对应ASCII码";
CM_ SG_ 2499866222 D2P_Cfg1_SW_Ver_Byte6_46 "DCDC软件版本号Byte6对应ASCII码";
CM_ SG_ 2499866222 D2P_Cfg1_SW_Ver_Byte7_46 "DCDC软件版本号Byte7对应ASCII码";
CM_ SG_ 2499866223 D2P_Cfg1_SW_Ver_Byte0_47 "DCDC软件版本号最低字节Byte0对应ASCII码";
CM_ SG_ 2499866223 D2P_Cfg1_SW_Ver_Byte1_47 "DCDC软件版本号Byte1对应ASCII码";
CM_ SG_ 2499866223 D2P_Cfg1_SW_Ver_Byte2_47 "DCDC软件版本号Byte2对应ASCII码";
CM_ SG_ 2499866223 D2P_Cfg1_SW_Ver_Byte3_47 "DCDC软件版本号Byte3对应ASCII码";
CM_ SG_ 2499866223 D2P_Cfg1_SW_Ver_Byte4_47 "DCDC软件版本号Byte4对应ASCII码";
CM_ SG_ 2499866223 D2P_Cfg1_SW_Ver_Byte5_47 "DCDC软件版本号Byte5对应ASCII码";
CM_ SG_ 2499866223 D2P_Cfg1_SW_Ver_Byte6_47 "DCDC软件版本号Byte6对应ASCII码";
CM_ SG_ 2499866223 D2P_Cfg1_SW_Ver_Byte7_47 "DCDC软件版本号Byte7对应ASCII码";
CM_ SG_ 2499866224 D2P_Cfg1_SW_Ver_Byte0_48 "DCDC软件版本号最低字节Byte0对应ASCII码";
CM_ SG_ 2499866224 D2P_Cfg1_SW_Ver_Byte1_48 "DCDC软件版本号Byte1对应ASCII码";
CM_ SG_ 2499866224 D2P_Cfg1_SW_Ver_Byte2_48 "DCDC软件版本号Byte2对应ASCII码";
CM_ SG_ 2499866224 D2P_Cfg1_SW_Ver_Byte3_48 "DCDC软件版本号Byte3对应ASCII码";
CM_ SG_ 2499866224 D2P_Cfg1_SW_Ver_Byte4_48 "DCDC软件版本号Byte4对应ASCII码";
CM_ SG_ 2499866224 D2P_Cfg1_SW_Ver_Byte5_48 "DCDC软件版本号Byte5对应ASCII码";
CM_ SG_ 2499866224 D2P_Cfg1_SW_Ver_Byte6_48 "DCDC软件版本号Byte6对应ASCII码";
CM_ SG_ 2499866224 D2P_Cfg1_SW_Ver_Byte7_48 "DCDC软件版本号Byte7对应ASCII码";
CM_ SG_ 2499866225 D2P_Cfg1_SW_Ver_Byte0_49 "DCDC软件版本号最低字节Byte0对应ASCII码";
CM_ SG_ 2499866225 D2P_Cfg1_SW_Ver_Byte1_49 "DCDC软件版本号Byte1对应ASCII码";
CM_ SG_ 2499866225 D2P_Cfg1_SW_Ver_Byte2_49 "DCDC软件版本号Byte2对应ASCII码";
CM_ SG_ 2499866225 D2P_Cfg1_SW_Ver_Byte3_49 "DCDC软件版本号Byte3对应ASCII码";
CM_ SG_ 2499866225 D2P_Cfg1_SW_Ver_Byte4_49 "DCDC软件版本号Byte4对应ASCII码";
CM_ SG_ 2499866225 D2P_Cfg1_SW_Ver_Byte5_49 "DCDC软件版本号Byte5对应ASCII码";
CM_ SG_ 2499866225 D2P_Cfg1_SW_Ver_Byte6_49 "DCDC软件版本号Byte6对应ASCII码";
CM_ SG_ 2499866225 D2P_Cfg1_SW_Ver_Byte7_49 "DCDC软件版本号Byte7对应ASCII码";
CM_ SG_ 2499866226 D2P_Cfg1_SW_Ver_Byte0_50 "DCDC软件版本号最低字节Byte0对应ASCII码";
CM_ SG_ 2499866226 D2P_Cfg1_SW_Ver_Byte1_50 "DCDC软件版本号Byte1对应ASCII码";
CM_ SG_ 2499866226 D2P_Cfg1_SW_Ver_Byte2_50 "DCDC软件版本号Byte2对应ASCII码";
CM_ SG_ 2499866226 D2P_Cfg1_SW_Ver_Byte3_50 "DCDC软件版本号Byte3对应ASCII码";
CM_ SG_ 2499866226 D2P_Cfg1_SW_Ver_Byte4_50 "DCDC软件版本号Byte4对应ASCII码";
CM_ SG_ 2499866226 D2P_Cfg1_SW_Ver_Byte5_50 "DCDC软件版本号Byte5对应ASCII码";
CM_ SG_ 2499866226 D2P_Cfg1_SW_Ver_Byte6_50 "DCDC软件版本号Byte6对应ASCII码";
CM_ SG_ 2499866226 D2P_Cfg1_SW_Ver_Byte7_50 "DCDC软件版本号Byte7对应ASCII码";
CM_ SG_ 2499866227 D2P_Cfg1_SW_Ver_Byte0_51 "DCDC软件版本号最低字节Byte0对应ASCII码";
CM_ SG_ 2499866227 D2P_Cfg1_SW_Ver_Byte1_51 "DCDC软件版本号Byte1对应ASCII码";
CM_ SG_ 2499866227 D2P_Cfg1_SW_Ver_Byte2_51 "DCDC软件版本号Byte2对应ASCII码";
CM_ SG_ 2499866227 D2P_Cfg1_SW_Ver_Byte3_51 "DCDC软件版本号Byte3对应ASCII码";
CM_ SG_ 2499866227 D2P_Cfg1_SW_Ver_Byte4_51 "DCDC软件版本号Byte4对应ASCII码";
CM_ SG_ 2499866227 D2P_Cfg1_SW_Ver_Byte5_51 "DCDC软件版本号Byte5对应ASCII码";
CM_ SG_ 2499866227 D2P_Cfg1_SW_Ver_Byte6_51 "DCDC软件版本号Byte6对应ASCII码";
CM_ SG_ 2499866227 D2P_Cfg1_SW_Ver_Byte7_51 "DCDC软件版本号Byte7对应ASCII码";
CM_ SG_ 2499866228 D2P_Cfg1_SW_Ver_Byte0_52 "DCDC软件版本号最低字节Byte0对应ASCII码";
CM_ SG_ 2499866228 D2P_Cfg1_SW_Ver_Byte1_52 "DCDC软件版本号Byte1对应ASCII码";
CM_ SG_ 2499866228 D2P_Cfg1_SW_Ver_Byte2_52 "DCDC软件版本号Byte2对应ASCII码";
CM_ SG_ 2499866228 D2P_Cfg1_SW_Ver_Byte3_52 "DCDC软件版本号Byte3对应ASCII码";
CM_ SG_ 2499866228 D2P_Cfg1_SW_Ver_Byte4_52 "DCDC软件版本号Byte4对应ASCII码";
CM_ SG_ 2499866228 D2P_Cfg1_SW_Ver_Byte5_52 "DCDC软件版本号Byte5对应ASCII码";
CM_ SG_ 2499866228 D2P_Cfg1_SW_Ver_Byte6_52 "DCDC软件版本号Byte6对应ASCII码";
CM_ SG_ 2499866228 D2P_Cfg1_SW_Ver_Byte7_52 "DCDC软件版本号Byte7对应ASCII码";
CM_ SG_ 2499866229 D2P_Cfg1_SW_Ver_Byte0_53 "DCDC软件版本号最低字节Byte0对应ASCII码";
CM_ SG_ 2499866229 D2P_Cfg1_SW_Ver_Byte1_53 "DCDC软件版本号Byte1对应ASCII码";
CM_ SG_ 2499866229 D2P_Cfg1_SW_Ver_Byte2_53 "DCDC软件版本号Byte2对应ASCII码";
CM_ SG_ 2499866229 D2P_Cfg1_SW_Ver_Byte3_53 "DCDC软件版本号Byte3对应ASCII码";
CM_ SG_ 2499866229 D2P_Cfg1_SW_Ver_Byte4_53 "DCDC软件版本号Byte4对应ASCII码";
CM_ SG_ 2499866229 D2P_Cfg1_SW_Ver_Byte5_53 "DCDC软件版本号Byte5对应ASCII码";
CM_ SG_ 2499866229 D2P_Cfg1_SW_Ver_Byte6_53 "DCDC软件版本号Byte6对应ASCII码";
CM_ SG_ 2499866229 D2P_Cfg1_SW_Ver_Byte7_53 "DCDC软件版本号Byte7对应ASCII码";
CM_ SG_ 2499866230 D2P_Cfg1_SW_Ver_Byte0_54 "DCDC软件版本号最低字节Byte0对应ASCII码";
CM_ SG_ 2499866230 D2P_Cfg1_SW_Ver_Byte1_54 "DCDC软件版本号Byte1对应ASCII码";
CM_ SG_ 2499866230 D2P_Cfg1_SW_Ver_Byte2_54 "DCDC软件版本号Byte2对应ASCII码";
CM_ SG_ 2499866230 D2P_Cfg1_SW_Ver_Byte3_54 "DCDC软件版本号Byte3对应ASCII码";
CM_ SG_ 2499866230 D2P_Cfg1_SW_Ver_Byte4_54 "DCDC软件版本号Byte4对应ASCII码";
CM_ SG_ 2499866230 D2P_Cfg1_SW_Ver_Byte5_54 "DCDC软件版本号Byte5对应ASCII码";
CM_ SG_ 2499866230 D2P_Cfg1_SW_Ver_Byte6_54 "DCDC软件版本号Byte6对应ASCII码";
CM_ SG_ 2499866230 D2P_Cfg1_SW_Ver_Byte7_54 "DCDC软件版本号Byte7对应ASCII码";
CM_ SG_ 2499866231 D2P_Cfg1_SW_Ver_Byte0_55 "DCDC软件版本号最低字节Byte0对应ASCII码";
CM_ SG_ 2499866231 D2P_Cfg1_SW_Ver_Byte1_55 "DCDC软件版本号Byte1对应ASCII码";
CM_ SG_ 2499866231 D2P_Cfg1_SW_Ver_Byte2_55 "DCDC软件版本号Byte2对应ASCII码";
CM_ SG_ 2499866231 D2P_Cfg1_SW_Ver_Byte3_55 "DCDC软件版本号Byte3对应ASCII码";
CM_ SG_ 2499866231 D2P_Cfg1_SW_Ver_Byte4_55 "DCDC软件版本号Byte4对应ASCII码";
CM_ SG_ 2499866231 D2P_Cfg1_SW_Ver_Byte5_55 "DCDC软件版本号Byte5对应ASCII码";
CM_ SG_ 2499866231 D2P_Cfg1_SW_Ver_Byte6_55 "DCDC软件版本号Byte6对应ASCII码";
CM_ SG_ 2499866231 D2P_Cfg1_SW_Ver_Byte7_55 "DCDC软件版本号Byte7对应ASCII码";
CM_ SG_ 2499866232 D2P_Cfg1_SW_Ver_Byte0_56 "DCDC软件版本号最低字节Byte0对应ASCII码";
CM_ SG_ 2499866232 D2P_Cfg1_SW_Ver_Byte1_56 "DCDC软件版本号Byte1对应ASCII码";
CM_ SG_ 2499866232 D2P_Cfg1_SW_Ver_Byte2_56 "DCDC软件版本号Byte2对应ASCII码";
CM_ SG_ 2499866232 D2P_Cfg1_SW_Ver_Byte3_56 "DCDC软件版本号Byte3对应ASCII码";
CM_ SG_ 2499866232 D2P_Cfg1_SW_Ver_Byte4_56 "DCDC软件版本号Byte4对应ASCII码";
CM_ SG_ 2499866232 D2P_Cfg1_SW_Ver_Byte5_56 "DCDC软件版本号Byte5对应ASCII码";
CM_ SG_ 2499866232 D2P_Cfg1_SW_Ver_Byte6_56 "DCDC软件版本号Byte6对应ASCII码";
CM_ SG_ 2499866232 D2P_Cfg1_SW_Ver_Byte7_56 "DCDC软件版本号Byte7对应ASCII码";
CM_ SG_ 2499866233 D2P_Cfg1_SW_Ver_Byte0_57 "DCDC软件版本号最低字节Byte0对应ASCII码";
CM_ SG_ 2499866233 D2P_Cfg1_SW_Ver_Byte1_57 "DCDC软件版本号Byte1对应ASCII码";
CM_ SG_ 2499866233 D2P_Cfg1_SW_Ver_Byte2_57 "DCDC软件版本号Byte2对应ASCII码";
CM_ SG_ 2499866233 D2P_Cfg1_SW_Ver_Byte3_57 "DCDC软件版本号Byte3对应ASCII码";
CM_ SG_ 2499866233 D2P_Cfg1_SW_Ver_Byte4_57 "DCDC软件版本号Byte4对应ASCII码";
CM_ SG_ 2499866233 D2P_Cfg1_SW_Ver_Byte5_57 "DCDC软件版本号Byte5对应ASCII码";
CM_ SG_ 2499866233 D2P_Cfg1_SW_Ver_Byte6_57 "DCDC软件版本号Byte6对应ASCII码";
CM_ SG_ 2499866233 D2P_Cfg1_SW_Ver_Byte7_57 "DCDC软件版本号Byte7对应ASCII码";
CM_ SG_ 2499866234 D2P_Cfg1_SW_Ver_Byte0_58 "DCDC软件版本号最低字节Byte0对应ASCII码";
CM_ SG_ 2499866234 D2P_Cfg1_SW_Ver_Byte1_58 "DCDC软件版本号Byte1对应ASCII码";
CM_ SG_ 2499866234 D2P_Cfg1_SW_Ver_Byte2_58 "DCDC软件版本号Byte2对应ASCII码";
CM_ SG_ 2499866234 D2P_Cfg1_SW_Ver_Byte3_58 "DCDC软件版本号Byte3对应ASCII码";
CM_ SG_ 2499866234 D2P_Cfg1_SW_Ver_Byte4_58 "DCDC软件版本号Byte4对应ASCII码";
CM_ SG_ 2499866234 D2P_Cfg1_SW_Ver_Byte5_58 "DCDC软件版本号Byte5对应ASCII码";
CM_ SG_ 2499866234 D2P_Cfg1_SW_Ver_Byte6_58 "DCDC软件版本号Byte6对应ASCII码";
CM_ SG_ 2499866234 D2P_Cfg1_SW_Ver_Byte7_58 "DCDC软件版本号Byte7对应ASCII码";
CM_ SG_ 2499866235 D2P_Cfg1_SW_Ver_Byte0_59 "DCDC软件版本号最低字节Byte0对应ASCII码";
CM_ SG_ 2499866235 D2P_Cfg1_SW_Ver_Byte1_59 "DCDC软件版本号Byte1对应ASCII码";
CM_ SG_ 2499866235 D2P_Cfg1_SW_Ver_Byte2_59 "DCDC软件版本号Byte2对应ASCII码";
CM_ SG_ 2499866235 D2P_Cfg1_SW_Ver_Byte3_59 "DCDC软件版本号Byte3对应ASCII码";
CM_ SG_ 2499866235 D2P_Cfg1_SW_Ver_Byte4_59 "DCDC软件版本号Byte4对应ASCII码";
CM_ SG_ 2499866235 D2P_Cfg1_SW_Ver_Byte5_59 "DCDC软件版本号Byte5对应ASCII码";
CM_ SG_ 2499866235 D2P_Cfg1_SW_Ver_Byte6_59 "DCDC软件版本号Byte6对应ASCII码";
CM_ SG_ 2499866235 D2P_Cfg1_SW_Ver_Byte7_59 "DCDC软件版本号Byte7对应ASCII码";
CM_ SG_ 2499866236 D2P_Cfg1_SW_Ver_Byte0_60 "DCDC软件版本号最低字节Byte0对应ASCII码";
CM_ SG_ 2499866236 D2P_Cfg1_SW_Ver_Byte1_60 "DCDC软件版本号Byte1对应ASCII码";
CM_ SG_ 2499866236 D2P_Cfg1_SW_Ver_Byte2_60 "DCDC软件版本号Byte2对应ASCII码";
CM_ SG_ 2499866236 D2P_Cfg1_SW_Ver_Byte3_60 "DCDC软件版本号Byte3对应ASCII码";
CM_ SG_ 2499866236 D2P_Cfg1_SW_Ver_Byte4_60 "DCDC软件版本号Byte4对应ASCII码";
CM_ SG_ 2499866236 D2P_Cfg1_SW_Ver_Byte5_60 "DCDC软件版本号Byte5对应ASCII码";
CM_ SG_ 2499866236 D2P_Cfg1_SW_Ver_Byte6_60 "DCDC软件版本号Byte6对应ASCII码";
CM_ SG_ 2499866236 D2P_Cfg1_SW_Ver_Byte7_60 "DCDC软件版本号Byte7对应ASCII码";
CM_ SG_ 2499866237 D2P_Cfg1_SW_Ver_Byte0_61 "DCDC软件版本号最低字节Byte0对应ASCII码";
CM_ SG_ 2499866237 D2P_Cfg1_SW_Ver_Byte1_61 "DCDC软件版本号Byte1对应ASCII码";
CM_ SG_ 2499866237 D2P_Cfg1_SW_Ver_Byte2_61 "DCDC软件版本号Byte2对应ASCII码";
CM_ SG_ 2499866237 D2P_Cfg1_SW_Ver_Byte3_61 "DCDC软件版本号Byte3对应ASCII码";
CM_ SG_ 2499866237 D2P_Cfg1_SW_Ver_Byte4_61 "DCDC软件版本号Byte4对应ASCII码";
CM_ SG_ 2499866237 D2P_Cfg1_SW_Ver_Byte5_61 "DCDC软件版本号Byte5对应ASCII码";
CM_ SG_ 2499866237 D2P_Cfg1_SW_Ver_Byte6_61 "DCDC软件版本号Byte6对应ASCII码";
CM_ SG_ 2499866237 D2P_Cfg1_SW_Ver_Byte7_61 "DCDC软件版本号Byte7对应ASCII码";
CM_ SG_ 2499866238 D2P_Cfg1_SW_Ver_Byte0_62 "DCDC软件版本号最低字节Byte0对应ASCII码";
CM_ SG_ 2499866238 D2P_Cfg1_SW_Ver_Byte1_62 "DCDC软件版本号Byte1对应ASCII码";
CM_ SG_ 2499866238 D2P_Cfg1_SW_Ver_Byte2_62 "DCDC软件版本号Byte2对应ASCII码";
CM_ SG_ 2499866238 D2P_Cfg1_SW_Ver_Byte3_62 "DCDC软件版本号Byte3对应ASCII码";
CM_ SG_ 2499866238 D2P_Cfg1_SW_Ver_Byte4_62 "DCDC软件版本号Byte4对应ASCII码";
CM_ SG_ 2499866238 D2P_Cfg1_SW_Ver_Byte5_62 "DCDC软件版本号Byte5对应ASCII码";
CM_ SG_ 2499866238 D2P_Cfg1_SW_Ver_Byte6_62 "DCDC软件版本号Byte6对应ASCII码";
CM_ SG_ 2499866238 D2P_Cfg1_SW_Ver_Byte7_62 "DCDC软件版本号Byte7对应ASCII码";
CM_ SG_ 2499866239 D2P_Cfg1_SW_Ver_Byte0_63 "DCDC软件版本号最低字节Byte0对应ASCII码";
CM_ SG_ 2499866239 D2P_Cfg1_SW_Ver_Byte1_63 "DCDC软件版本号Byte1对应ASCII码";
CM_ SG_ 2499866239 D2P_Cfg1_SW_Ver_Byte2_63 "DCDC软件版本号Byte2对应ASCII码";
CM_ SG_ 2499866239 D2P_Cfg1_SW_Ver_Byte3_63 "DCDC软件版本号Byte3对应ASCII码";
CM_ SG_ 2499866239 D2P_Cfg1_SW_Ver_Byte4_63 "DCDC软件版本号Byte4对应ASCII码";
CM_ SG_ 2499866239 D2P_Cfg1_SW_Ver_Byte5_63 "DCDC软件版本号Byte5对应ASCII码";
CM_ SG_ 2499866239 D2P_Cfg1_SW_Ver_Byte6_63 "DCDC软件版本号Byte6对应ASCII码";
CM_ SG_ 2499866239 D2P_Cfg1_SW_Ver_Byte7_63 "DCDC软件版本号Byte7对应ASCII码";
CM_ SG_ 2499931713 D2P_Cfg2_SW_Ver_Byte8_01 "DCDC软件版本号Byte8对应ASCII码";
CM_ SG_ 2499931713 D2P_Cfg2_SW_Ver_Byte9_01 "DCDC软件版本号Byte9对应ASCII码";
CM_ SG_ 2499931713 D2P_Cfg2_SW_Ver_Byte10_01 "DCDC软件版本号Byte10对应ASCII码";
CM_ SG_ 2499931713 D2P_Cfg2_SW_Ver_Byte11_01 "DCDC软件版本号Byte11对应ASCII码";
CM_ SG_ 2499931713 D2P_Cfg2_SW_Ver_Byte12_01 "DCDC软件版本号Byte12对应ASCII码";
CM_ SG_ 2499931713 D2P_Cfg2_SW_Ver_Byte13_01 "DCDC软件版本号Byte13对应ASCII码";
CM_ SG_ 2499931713 D2P_Cfg2_SW_Ver_Byte14_01 "DCDC软件版本号Byte14对应ASCII码";
CM_ SG_ 2499931713 D2P_Cfg2_SW_Ver_Byte15_01 "DCDC软件版本号最高字节Byte15对应ASCII码";
CM_ SG_ 2499931714 D2P_Cfg2_SW_Ver_Byte8_02 "DCDC软件版本号Byte8对应ASCII码";
CM_ SG_ 2499931714 D2P_Cfg2_SW_Ver_Byte9_02 "DCDC软件版本号Byte9对应ASCII码";
CM_ SG_ 2499931714 D2P_Cfg2_SW_Ver_Byte10_02 "DCDC软件版本号Byte10对应ASCII码";
CM_ SG_ 2499931714 D2P_Cfg2_SW_Ver_Byte11_02 "DCDC软件版本号Byte11对应ASCII码";
CM_ SG_ 2499931714 D2P_Cfg2_SW_Ver_Byte12_02 "DCDC软件版本号Byte12对应ASCII码";
CM_ SG_ 2499931714 D2P_Cfg2_SW_Ver_Byte13_02 "DCDC软件版本号Byte13对应ASCII码";
CM_ SG_ 2499931714 D2P_Cfg2_SW_Ver_Byte14_02 "DCDC软件版本号Byte14对应ASCII码";
CM_ SG_ 2499931714 D2P_Cfg2_SW_Ver_Byte15_02 "DCDC软件版本号最高字节Byte15对应ASCII码";
CM_ SG_ 2499931715 D2P_Cfg2_SW_Ver_Byte8_03 "DCDC软件版本号Byte8对应ASCII码";
CM_ SG_ 2499931715 D2P_Cfg2_SW_Ver_Byte9_03 "DCDC软件版本号Byte9对应ASCII码";
CM_ SG_ 2499931715 D2P_Cfg2_SW_Ver_Byte10_03 "DCDC软件版本号Byte10对应ASCII码";
CM_ SG_ 2499931715 D2P_Cfg2_SW_Ver_Byte11_03 "DCDC软件版本号Byte11对应ASCII码";
CM_ SG_ 2499931715 D2P_Cfg2_SW_Ver_Byte12_03 "DCDC软件版本号Byte12对应ASCII码";
CM_ SG_ 2499931715 D2P_Cfg2_SW_Ver_Byte13_03 "DCDC软件版本号Byte13对应ASCII码";
CM_ SG_ 2499931715 D2P_Cfg2_SW_Ver_Byte14_03 "DCDC软件版本号Byte14对应ASCII码";
CM_ SG_ 2499931715 D2P_Cfg2_SW_Ver_Byte15_03 "DCDC软件版本号最高字节Byte15对应ASCII码";
CM_ SG_ 2499931716 D2P_Cfg2_SW_Ver_Byte8_04 "DCDC软件版本号Byte8对应ASCII码";
CM_ SG_ 2499931716 D2P_Cfg2_SW_Ver_Byte9_04 "DCDC软件版本号Byte9对应ASCII码";
CM_ SG_ 2499931716 D2P_Cfg2_SW_Ver_Byte10_04 "DCDC软件版本号Byte10对应ASCII码";
CM_ SG_ 2499931716 D2P_Cfg2_SW_Ver_Byte11_04 "DCDC软件版本号Byte11对应ASCII码";
CM_ SG_ 2499931716 D2P_Cfg2_SW_Ver_Byte12_04 "DCDC软件版本号Byte12对应ASCII码";
CM_ SG_ 2499931716 D2P_Cfg2_SW_Ver_Byte13_04 "DCDC软件版本号Byte13对应ASCII码";
CM_ SG_ 2499931716 D2P_Cfg2_SW_Ver_Byte14_04 "DCDC软件版本号Byte14对应ASCII码";
CM_ SG_ 2499931716 D2P_Cfg2_SW_Ver_Byte15_04 "DCDC软件版本号最高字节Byte15对应ASCII码";
CM_ SG_ 2499931717 D2P_Cfg2_SW_Ver_Byte8_05 "DCDC软件版本号Byte8对应ASCII码";
CM_ SG_ 2499931717 D2P_Cfg2_SW_Ver_Byte9_05 "DCDC软件版本号Byte9对应ASCII码";
CM_ SG_ 2499931717 D2P_Cfg2_SW_Ver_Byte10_05 "DCDC软件版本号Byte10对应ASCII码";
CM_ SG_ 2499931717 D2P_Cfg2_SW_Ver_Byte11_05 "DCDC软件版本号Byte11对应ASCII码";
CM_ SG_ 2499931717 D2P_Cfg2_SW_Ver_Byte12_05 "DCDC软件版本号Byte12对应ASCII码";
CM_ SG_ 2499931717 D2P_Cfg2_SW_Ver_Byte13_05 "DCDC软件版本号Byte13对应ASCII码";
CM_ SG_ 2499931717 D2P_Cfg2_SW_Ver_Byte14_05 "DCDC软件版本号Byte14对应ASCII码";
CM_ SG_ 2499931717 D2P_Cfg2_SW_Ver_Byte15_05 "DCDC软件版本号最高字节Byte15对应ASCII码";
CM_ SG_ 2499931718 D2P_Cfg2_SW_Ver_Byte8_06 "DCDC软件版本号Byte8对应ASCII码";
CM_ SG_ 2499931718 D2P_Cfg2_SW_Ver_Byte9_06 "DCDC软件版本号Byte9对应ASCII码";
CM_ SG_ 2499931718 D2P_Cfg2_SW_Ver_Byte10_06 "DCDC软件版本号Byte10对应ASCII码";
CM_ SG_ 2499931718 D2P_Cfg2_SW_Ver_Byte11_06 "DCDC软件版本号Byte11对应ASCII码";
CM_ SG_ 2499931718 D2P_Cfg2_SW_Ver_Byte12_06 "DCDC软件版本号Byte12对应ASCII码";
CM_ SG_ 2499931718 D2P_Cfg2_SW_Ver_Byte13_06 "DCDC软件版本号Byte13对应ASCII码";
CM_ SG_ 2499931718 D2P_Cfg2_SW_Ver_Byte14_06 "DCDC软件版本号Byte14对应ASCII码";
CM_ SG_ 2499931718 D2P_Cfg2_SW_Ver_Byte15_06 "DCDC软件版本号最高字节Byte15对应ASCII码";
CM_ SG_ 2499931719 D2P_Cfg2_SW_Ver_Byte8_07 "DCDC软件版本号Byte8对应ASCII码";
CM_ SG_ 2499931719 D2P_Cfg2_SW_Ver_Byte9_07 "DCDC软件版本号Byte9对应ASCII码";
CM_ SG_ 2499931719 D2P_Cfg2_SW_Ver_Byte10_07 "DCDC软件版本号Byte10对应ASCII码";
CM_ SG_ 2499931719 D2P_Cfg2_SW_Ver_Byte11_07 "DCDC软件版本号Byte11对应ASCII码";
CM_ SG_ 2499931719 D2P_Cfg2_SW_Ver_Byte12_07 "DCDC软件版本号Byte12对应ASCII码";
CM_ SG_ 2499931719 D2P_Cfg2_SW_Ver_Byte13_07 "DCDC软件版本号Byte13对应ASCII码";
CM_ SG_ 2499931719 D2P_Cfg2_SW_Ver_Byte14_07 "DCDC软件版本号Byte14对应ASCII码";
CM_ SG_ 2499931719 D2P_Cfg2_SW_Ver_Byte15_07 "DCDC软件版本号最高字节Byte15对应ASCII码";
CM_ SG_ 2499931720 D2P_Cfg2_SW_Ver_Byte8_08 "DCDC软件版本号Byte8对应ASCII码";
CM_ SG_ 2499931720 D2P_Cfg2_SW_Ver_Byte9_08 "DCDC软件版本号Byte9对应ASCII码";
CM_ SG_ 2499931720 D2P_Cfg2_SW_Ver_Byte10_08 "DCDC软件版本号Byte10对应ASCII码";
CM_ SG_ 2499931720 D2P_Cfg2_SW_Ver_Byte11_08 "DCDC软件版本号Byte11对应ASCII码";
CM_ SG_ 2499931720 D2P_Cfg2_SW_Ver_Byte12_08 "DCDC软件版本号Byte12对应ASCII码";
CM_ SG_ 2499931720 D2P_Cfg2_SW_Ver_Byte13_08 "DCDC软件版本号Byte13对应ASCII码";
CM_ SG_ 2499931720 D2P_Cfg2_SW_Ver_Byte14_08 "DCDC软件版本号Byte14对应ASCII码";
CM_ SG_ 2499931720 D2P_Cfg2_SW_Ver_Byte15_08 "DCDC软件版本号最高字节Byte15对应ASCII码";
CM_ SG_ 2499931721 D2P_Cfg2_SW_Ver_Byte8_09 "DCDC软件版本号Byte8对应ASCII码";
CM_ SG_ 2499931721 D2P_Cfg2_SW_Ver_Byte9_09 "DCDC软件版本号Byte9对应ASCII码";
CM_ SG_ 2499931721 D2P_Cfg2_SW_Ver_Byte10_09 "DCDC软件版本号Byte10对应ASCII码";
CM_ SG_ 2499931721 D2P_Cfg2_SW_Ver_Byte11_09 "DCDC软件版本号Byte11对应ASCII码";
CM_ SG_ 2499931721 D2P_Cfg2_SW_Ver_Byte12_09 "DCDC软件版本号Byte12对应ASCII码";
CM_ SG_ 2499931721 D2P_Cfg2_SW_Ver_Byte13_09 "DCDC软件版本号Byte13对应ASCII码";
CM_ SG_ 2499931721 D2P_Cfg2_SW_Ver_Byte14_09 "DCDC软件版本号Byte14对应ASCII码";
CM_ SG_ 2499931721 D2P_Cfg2_SW_Ver_Byte15_09 "DCDC软件版本号最高字节Byte15对应ASCII码";
CM_ SG_ 2499931722 D2P_Cfg2_SW_Ver_Byte8_10 "DCDC软件版本号Byte8对应ASCII码";
CM_ SG_ 2499931722 D2P_Cfg2_SW_Ver_Byte9_10 "DCDC软件版本号Byte9对应ASCII码";
CM_ SG_ 2499931722 D2P_Cfg2_SW_Ver_Byte10_10 "DCDC软件版本号Byte10对应ASCII码";
CM_ SG_ 2499931722 D2P_Cfg2_SW_Ver_Byte11_10 "DCDC软件版本号Byte11对应ASCII码";
CM_ SG_ 2499931722 D2P_Cfg2_SW_Ver_Byte12_10 "DCDC软件版本号Byte12对应ASCII码";
CM_ SG_ 2499931722 D2P_Cfg2_SW_Ver_Byte13_10 "DCDC软件版本号Byte13对应ASCII码";
CM_ SG_ 2499931722 D2P_Cfg2_SW_Ver_Byte14_10 "DCDC软件版本号Byte14对应ASCII码";
CM_ SG_ 2499931722 D2P_Cfg2_SW_Ver_Byte15_10 "DCDC软件版本号最高字节Byte15对应ASCII码";
CM_ SG_ 2499931723 D2P_Cfg2_SW_Ver_Byte8_11 "DCDC软件版本号Byte8对应ASCII码";
CM_ SG_ 2499931723 D2P_Cfg2_SW_Ver_Byte9_11 "DCDC软件版本号Byte9对应ASCII码";
CM_ SG_ 2499931723 D2P_Cfg2_SW_Ver_Byte10_11 "DCDC软件版本号Byte10对应ASCII码";
CM_ SG_ 2499931723 D2P_Cfg2_SW_Ver_Byte11_11 "DCDC软件版本号Byte11对应ASCII码";
CM_ SG_ 2499931723 D2P_Cfg2_SW_Ver_Byte12_11 "DCDC软件版本号Byte12对应ASCII码";
CM_ SG_ 2499931723 D2P_Cfg2_SW_Ver_Byte13_11 "DCDC软件版本号Byte13对应ASCII码";
CM_ SG_ 2499931723 D2P_Cfg2_SW_Ver_Byte14_11 "DCDC软件版本号Byte14对应ASCII码";
CM_ SG_ 2499931723 D2P_Cfg2_SW_Ver_Byte15_11 "DCDC软件版本号最高字节Byte15对应ASCII码";
CM_ SG_ 2499931724 D2P_Cfg2_SW_Ver_Byte8_12 "DCDC软件版本号Byte8对应ASCII码";
CM_ SG_ 2499931724 D2P_Cfg2_SW_Ver_Byte9_12 "DCDC软件版本号Byte9对应ASCII码";
CM_ SG_ 2499931724 D2P_Cfg2_SW_Ver_Byte10_12 "DCDC软件版本号Byte10对应ASCII码";
CM_ SG_ 2499931724 D2P_Cfg2_SW_Ver_Byte11_12 "DCDC软件版本号Byte11对应ASCII码";
CM_ SG_ 2499931724 D2P_Cfg2_SW_Ver_Byte12_12 "DCDC软件版本号Byte12对应ASCII码";
CM_ SG_ 2499931724 D2P_Cfg2_SW_Ver_Byte13_12 "DCDC软件版本号Byte13对应ASCII码";
CM_ SG_ 2499931724 D2P_Cfg2_SW_Ver_Byte14_12 "DCDC软件版本号Byte14对应ASCII码";
CM_ SG_ 2499931724 D2P_Cfg2_SW_Ver_Byte15_12 "DCDC软件版本号最高字节Byte15对应ASCII码";
CM_ SG_ 2499931725 D2P_Cfg2_SW_Ver_Byte8_13 "DCDC软件版本号Byte8对应ASCII码";
CM_ SG_ 2499931725 D2P_Cfg2_SW_Ver_Byte9_13 "DCDC软件版本号Byte9对应ASCII码";
CM_ SG_ 2499931725 D2P_Cfg2_SW_Ver_Byte10_13 "DCDC软件版本号Byte10对应ASCII码";
CM_ SG_ 2499931725 D2P_Cfg2_SW_Ver_Byte11_13 "DCDC软件版本号Byte11对应ASCII码";
CM_ SG_ 2499931725 D2P_Cfg2_SW_Ver_Byte12_13 "DCDC软件版本号Byte12对应ASCII码";
CM_ SG_ 2499931725 D2P_Cfg2_SW_Ver_Byte13_13 "DCDC软件版本号Byte13对应ASCII码";
CM_ SG_ 2499931725 D2P_Cfg2_SW_Ver_Byte14_13 "DCDC软件版本号Byte14对应ASCII码";
CM_ SG_ 2499931725 D2P_Cfg2_SW_Ver_Byte15_13 "DCDC软件版本号最高字节Byte15对应ASCII码";
CM_ SG_ 2499931726 D2P_Cfg2_SW_Ver_Byte8_14 "DCDC软件版本号Byte8对应ASCII码";
CM_ SG_ 2499931726 D2P_Cfg2_SW_Ver_Byte9_14 "DCDC软件版本号Byte9对应ASCII码";
CM_ SG_ 2499931726 D2P_Cfg2_SW_Ver_Byte10_14 "DCDC软件版本号Byte10对应ASCII码";
CM_ SG_ 2499931726 D2P_Cfg2_SW_Ver_Byte11_14 "DCDC软件版本号Byte11对应ASCII码";
CM_ SG_ 2499931726 D2P_Cfg2_SW_Ver_Byte12_14 "DCDC软件版本号Byte12对应ASCII码";
CM_ SG_ 2499931726 D2P_Cfg2_SW_Ver_Byte13_14 "DCDC软件版本号Byte13对应ASCII码";
CM_ SG_ 2499931726 D2P_Cfg2_SW_Ver_Byte14_14 "DCDC软件版本号Byte14对应ASCII码";
CM_ SG_ 2499931726 D2P_Cfg2_SW_Ver_Byte15_14 "DCDC软件版本号最高字节Byte15对应ASCII码";
CM_ SG_ 2499931727 D2P_Cfg2_SW_Ver_Byte8_15 "DCDC软件版本号Byte8对应ASCII码";
CM_ SG_ 2499931727 D2P_Cfg2_SW_Ver_Byte9_15 "DCDC软件版本号Byte9对应ASCII码";
CM_ SG_ 2499931727 D2P_Cfg2_SW_Ver_Byte10_15 "DCDC软件版本号Byte10对应ASCII码";
CM_ SG_ 2499931727 D2P_Cfg2_SW_Ver_Byte11_15 "DCDC软件版本号Byte11对应ASCII码";
CM_ SG_ 2499931727 D2P_Cfg2_SW_Ver_Byte12_15 "DCDC软件版本号Byte12对应ASCII码";
CM_ SG_ 2499931727 D2P_Cfg2_SW_Ver_Byte13_15 "DCDC软件版本号Byte13对应ASCII码";
CM_ SG_ 2499931727 D2P_Cfg2_SW_Ver_Byte14_15 "DCDC软件版本号Byte14对应ASCII码";
CM_ SG_ 2499931727 D2P_Cfg2_SW_Ver_Byte15_15 "DCDC软件版本号最高字节Byte15对应ASCII码";
CM_ SG_ 2499931728 D2P_Cfg2_SW_Ver_Byte8_16 "DCDC软件版本号Byte8对应ASCII码";
CM_ SG_ 2499931728 D2P_Cfg2_SW_Ver_Byte9_16 "DCDC软件版本号Byte9对应ASCII码";
CM_ SG_ 2499931728 D2P_Cfg2_SW_Ver_Byte10_16 "DCDC软件版本号Byte10对应ASCII码";
CM_ SG_ 2499931728 D2P_Cfg2_SW_Ver_Byte11_16 "DCDC软件版本号Byte11对应ASCII码";
CM_ SG_ 2499931728 D2P_Cfg2_SW_Ver_Byte12_16 "DCDC软件版本号Byte12对应ASCII码";
CM_ SG_ 2499931728 D2P_Cfg2_SW_Ver_Byte13_16 "DCDC软件版本号Byte13对应ASCII码";
CM_ SG_ 2499931728 D2P_Cfg2_SW_Ver_Byte14_16 "DCDC软件版本号Byte14对应ASCII码";
CM_ SG_ 2499931728 D2P_Cfg2_SW_Ver_Byte15_16 "DCDC软件版本号最高字节Byte15对应ASCII码";
CM_ SG_ 2499931729 D2P_Cfg2_SW_Ver_Byte8_17 "DCDC软件版本号Byte8对应ASCII码";
CM_ SG_ 2499931729 D2P_Cfg2_SW_Ver_Byte9_17 "DCDC软件版本号Byte9对应ASCII码";
CM_ SG_ 2499931729 D2P_Cfg2_SW_Ver_Byte10_17 "DCDC软件版本号Byte10对应ASCII码";
CM_ SG_ 2499931729 D2P_Cfg2_SW_Ver_Byte11_17 "DCDC软件版本号Byte11对应ASCII码";
CM_ SG_ 2499931729 D2P_Cfg2_SW_Ver_Byte12_17 "DCDC软件版本号Byte12对应ASCII码";
CM_ SG_ 2499931729 D2P_Cfg2_SW_Ver_Byte13_17 "DCDC软件版本号Byte13对应ASCII码";
CM_ SG_ 2499931729 D2P_Cfg2_SW_Ver_Byte14_17 "DCDC软件版本号Byte14对应ASCII码";
CM_ SG_ 2499931729 D2P_Cfg2_SW_Ver_Byte15_17 "DCDC软件版本号最高字节Byte15对应ASCII码";
CM_ SG_ 2499931730 D2P_Cfg2_SW_Ver_Byte8_18 "DCDC软件版本号Byte8对应ASCII码";
CM_ SG_ 2499931730 D2P_Cfg2_SW_Ver_Byte9_18 "DCDC软件版本号Byte9对应ASCII码";
CM_ SG_ 2499931730 D2P_Cfg2_SW_Ver_Byte10_18 "DCDC软件版本号Byte10对应ASCII码";
CM_ SG_ 2499931730 D2P_Cfg2_SW_Ver_Byte11_18 "DCDC软件版本号Byte11对应ASCII码";
CM_ SG_ 2499931730 D2P_Cfg2_SW_Ver_Byte12_18 "DCDC软件版本号Byte12对应ASCII码";
CM_ SG_ 2499931730 D2P_Cfg2_SW_Ver_Byte13_18 "DCDC软件版本号Byte13对应ASCII码";
CM_ SG_ 2499931730 D2P_Cfg2_SW_Ver_Byte14_18 "DCDC软件版本号Byte14对应ASCII码";
CM_ SG_ 2499931730 D2P_Cfg2_SW_Ver_Byte15_18 "DCDC软件版本号最高字节Byte15对应ASCII码";
CM_ SG_ 2499931731 D2P_Cfg2_SW_Ver_Byte8_19 "DCDC软件版本号Byte8对应ASCII码";
CM_ SG_ 2499931731 D2P_Cfg2_SW_Ver_Byte9_19 "DCDC软件版本号Byte9对应ASCII码";
CM_ SG_ 2499931731 D2P_Cfg2_SW_Ver_Byte10_19 "DCDC软件版本号Byte10对应ASCII码";
CM_ SG_ 2499931731 D2P_Cfg2_SW_Ver_Byte11_19 "DCDC软件版本号Byte11对应ASCII码";
CM_ SG_ 2499931731 D2P_Cfg2_SW_Ver_Byte12_19 "DCDC软件版本号Byte12对应ASCII码";
CM_ SG_ 2499931731 D2P_Cfg2_SW_Ver_Byte13_19 "DCDC软件版本号Byte13对应ASCII码";
CM_ SG_ 2499931731 D2P_Cfg2_SW_Ver_Byte14_19 "DCDC软件版本号Byte14对应ASCII码";
CM_ SG_ 2499931731 D2P_Cfg2_SW_Ver_Byte15_19 "DCDC软件版本号最高字节Byte15对应ASCII码";
CM_ SG_ 2499931732 D2P_Cfg2_SW_Ver_Byte8_20 "DCDC软件版本号Byte8对应ASCII码";
CM_ SG_ 2499931732 D2P_Cfg2_SW_Ver_Byte9_20 "DCDC软件版本号Byte9对应ASCII码";
CM_ SG_ 2499931732 D2P_Cfg2_SW_Ver_Byte10_20 "DCDC软件版本号Byte10对应ASCII码";
CM_ SG_ 2499931732 D2P_Cfg2_SW_Ver_Byte11_20 "DCDC软件版本号Byte11对应ASCII码";
CM_ SG_ 2499931732 D2P_Cfg2_SW_Ver_Byte12_20 "DCDC软件版本号Byte12对应ASCII码";
CM_ SG_ 2499931732 D2P_Cfg2_SW_Ver_Byte13_20 "DCDC软件版本号Byte13对应ASCII码";
CM_ SG_ 2499931732 D2P_Cfg2_SW_Ver_Byte14_20 "DCDC软件版本号Byte14对应ASCII码";
CM_ SG_ 2499931732 D2P_Cfg2_SW_Ver_Byte15_20 "DCDC软件版本号最高字节Byte15对应ASCII码";
CM_ SG_ 2499931733 D2P_Cfg2_SW_Ver_Byte8_21 "DCDC软件版本号Byte8对应ASCII码";
CM_ SG_ 2499931733 D2P_Cfg2_SW_Ver_Byte9_21 "DCDC软件版本号Byte9对应ASCII码";
CM_ SG_ 2499931733 D2P_Cfg2_SW_Ver_Byte10_21 "DCDC软件版本号Byte10对应ASCII码";
CM_ SG_ 2499931733 D2P_Cfg2_SW_Ver_Byte11_21 "DCDC软件版本号Byte11对应ASCII码";
CM_ SG_ 2499931733 D2P_Cfg2_SW_Ver_Byte12_21 "DCDC软件版本号Byte12对应ASCII码";
CM_ SG_ 2499931733 D2P_Cfg2_SW_Ver_Byte13_21 "DCDC软件版本号Byte13对应ASCII码";
CM_ SG_ 2499931733 D2P_Cfg2_SW_Ver_Byte14_21 "DCDC软件版本号Byte14对应ASCII码";
CM_ SG_ 2499931733 D2P_Cfg2_SW_Ver_Byte15_21 "DCDC软件版本号最高字节Byte15对应ASCII码";
CM_ SG_ 2499931734 D2P_Cfg2_SW_Ver_Byte8_22 "DCDC软件版本号Byte8对应ASCII码";
CM_ SG_ 2499931734 D2P_Cfg2_SW_Ver_Byte9_22 "DCDC软件版本号Byte9对应ASCII码";
CM_ SG_ 2499931734 D2P_Cfg2_SW_Ver_Byte10_22 "DCDC软件版本号Byte10对应ASCII码";
CM_ SG_ 2499931734 D2P_Cfg2_SW_Ver_Byte11_22 "DCDC软件版本号Byte11对应ASCII码";
CM_ SG_ 2499931734 D2P_Cfg2_SW_Ver_Byte12_22 "DCDC软件版本号Byte12对应ASCII码";
CM_ SG_ 2499931734 D2P_Cfg2_SW_Ver_Byte13_22 "DCDC软件版本号Byte13对应ASCII码";
CM_ SG_ 2499931734 D2P_Cfg2_SW_Ver_Byte14_22 "DCDC软件版本号Byte14对应ASCII码";
CM_ SG_ 2499931734 D2P_Cfg2_SW_Ver_Byte15_22 "DCDC软件版本号最高字节Byte15对应ASCII码";
CM_ SG_ 2499931735 D2P_Cfg2_SW_Ver_Byte8_23 "DCDC软件版本号Byte8对应ASCII码";
CM_ SG_ 2499931735 D2P_Cfg2_SW_Ver_Byte9_23 "DCDC软件版本号Byte9对应ASCII码";
CM_ SG_ 2499931735 D2P_Cfg2_SW_Ver_Byte10_23 "DCDC软件版本号Byte10对应ASCII码";
CM_ SG_ 2499931735 D2P_Cfg2_SW_Ver_Byte11_23 "DCDC软件版本号Byte11对应ASCII码";
CM_ SG_ 2499931735 D2P_Cfg2_SW_Ver_Byte12_23 "DCDC软件版本号Byte12对应ASCII码";
CM_ SG_ 2499931735 D2P_Cfg2_SW_Ver_Byte13_23 "DCDC软件版本号Byte13对应ASCII码";
CM_ SG_ 2499931735 D2P_Cfg2_SW_Ver_Byte14_23 "DCDC软件版本号Byte14对应ASCII码";
CM_ SG_ 2499931735 D2P_Cfg2_SW_Ver_Byte15_23 "DCDC软件版本号最高字节Byte15对应ASCII码";
CM_ SG_ 2499931736 D2P_Cfg2_SW_Ver_Byte8_24 "DCDC软件版本号Byte8对应ASCII码";
CM_ SG_ 2499931736 D2P_Cfg2_SW_Ver_Byte9_24 "DCDC软件版本号Byte9对应ASCII码";
CM_ SG_ 2499931736 D2P_Cfg2_SW_Ver_Byte10_24 "DCDC软件版本号Byte10对应ASCII码";
CM_ SG_ 2499931736 D2P_Cfg2_SW_Ver_Byte11_24 "DCDC软件版本号Byte11对应ASCII码";
CM_ SG_ 2499931736 D2P_Cfg2_SW_Ver_Byte12_24 "DCDC软件版本号Byte12对应ASCII码";
CM_ SG_ 2499931736 D2P_Cfg2_SW_Ver_Byte13_24 "DCDC软件版本号Byte13对应ASCII码";
CM_ SG_ 2499931736 D2P_Cfg2_SW_Ver_Byte14_24 "DCDC软件版本号Byte14对应ASCII码";
CM_ SG_ 2499931736 D2P_Cfg2_SW_Ver_Byte15_24 "DCDC软件版本号最高字节Byte15对应ASCII码";
CM_ SG_ 2499931737 D2P_Cfg2_SW_Ver_Byte8_25 "DCDC软件版本号Byte8对应ASCII码";
CM_ SG_ 2499931737 D2P_Cfg2_SW_Ver_Byte9_25 "DCDC软件版本号Byte9对应ASCII码";
CM_ SG_ 2499931737 D2P_Cfg2_SW_Ver_Byte10_25 "DCDC软件版本号Byte10对应ASCII码";
CM_ SG_ 2499931737 D2P_Cfg2_SW_Ver_Byte11_25 "DCDC软件版本号Byte11对应ASCII码";
CM_ SG_ 2499931737 D2P_Cfg2_SW_Ver_Byte12_25 "DCDC软件版本号Byte12对应ASCII码";
CM_ SG_ 2499931737 D2P_Cfg2_SW_Ver_Byte13_25 "DCDC软件版本号Byte13对应ASCII码";
CM_ SG_ 2499931737 D2P_Cfg2_SW_Ver_Byte14_25 "DCDC软件版本号Byte14对应ASCII码";
CM_ SG_ 2499931737 D2P_Cfg2_SW_Ver_Byte15_25 "DCDC软件版本号最高字节Byte15对应ASCII码";
CM_ SG_ 2499931738 D2P_Cfg2_SW_Ver_Byte8_26 "DCDC软件版本号Byte8对应ASCII码";
CM_ SG_ 2499931738 D2P_Cfg2_SW_Ver_Byte9_26 "DCDC软件版本号Byte9对应ASCII码";
CM_ SG_ 2499931738 D2P_Cfg2_SW_Ver_Byte10_26 "DCDC软件版本号Byte10对应ASCII码";
CM_ SG_ 2499931738 D2P_Cfg2_SW_Ver_Byte11_26 "DCDC软件版本号Byte11对应ASCII码";
CM_ SG_ 2499931738 D2P_Cfg2_SW_Ver_Byte12_26 "DCDC软件版本号Byte12对应ASCII码";
CM_ SG_ 2499931738 D2P_Cfg2_SW_Ver_Byte13_26 "DCDC软件版本号Byte13对应ASCII码";
CM_ SG_ 2499931738 D2P_Cfg2_SW_Ver_Byte14_26 "DCDC软件版本号Byte14对应ASCII码";
CM_ SG_ 2499931738 D2P_Cfg2_SW_Ver_Byte15_26 "DCDC软件版本号最高字节Byte15对应ASCII码";
CM_ SG_ 2499931739 D2P_Cfg2_SW_Ver_Byte8_27 "DCDC软件版本号Byte8对应ASCII码";
CM_ SG_ 2499931739 D2P_Cfg2_SW_Ver_Byte9_27 "DCDC软件版本号Byte9对应ASCII码";
CM_ SG_ 2499931739 D2P_Cfg2_SW_Ver_Byte10_27 "DCDC软件版本号Byte10对应ASCII码";
CM_ SG_ 2499931739 D2P_Cfg2_SW_Ver_Byte11_27 "DCDC软件版本号Byte11对应ASCII码";
CM_ SG_ 2499931739 D2P_Cfg2_SW_Ver_Byte12_27 "DCDC软件版本号Byte12对应ASCII码";
CM_ SG_ 2499931739 D2P_Cfg2_SW_Ver_Byte13_27 "DCDC软件版本号Byte13对应ASCII码";
CM_ SG_ 2499931739 D2P_Cfg2_SW_Ver_Byte14_27 "DCDC软件版本号Byte14对应ASCII码";
CM_ SG_ 2499931739 D2P_Cfg2_SW_Ver_Byte15_27 "DCDC软件版本号最高字节Byte15对应ASCII码";
CM_ SG_ 2499931740 D2P_Cfg2_SW_Ver_Byte8_28 "DCDC软件版本号Byte8对应ASCII码";
CM_ SG_ 2499931740 D2P_Cfg2_SW_Ver_Byte9_28 "DCDC软件版本号Byte9对应ASCII码";
CM_ SG_ 2499931740 D2P_Cfg2_SW_Ver_Byte10_28 "DCDC软件版本号Byte10对应ASCII码";
CM_ SG_ 2499931740 D2P_Cfg2_SW_Ver_Byte11_28 "DCDC软件版本号Byte11对应ASCII码";
CM_ SG_ 2499931740 D2P_Cfg2_SW_Ver_Byte12_28 "DCDC软件版本号Byte12对应ASCII码";
CM_ SG_ 2499931740 D2P_Cfg2_SW_Ver_Byte13_28 "DCDC软件版本号Byte13对应ASCII码";
CM_ SG_ 2499931740 D2P_Cfg2_SW_Ver_Byte14_28 "DCDC软件版本号Byte14对应ASCII码";
CM_ SG_ 2499931740 D2P_Cfg2_SW_Ver_Byte15_28 "DCDC软件版本号最高字节Byte15对应ASCII码";
CM_ SG_ 2499931741 D2P_Cfg2_SW_Ver_Byte8_29 "DCDC软件版本号Byte8对应ASCII码";
CM_ SG_ 2499931741 D2P_Cfg2_SW_Ver_Byte9_29 "DCDC软件版本号Byte9对应ASCII码";
CM_ SG_ 2499931741 D2P_Cfg2_SW_Ver_Byte10_29 "DCDC软件版本号Byte10对应ASCII码";
CM_ SG_ 2499931741 D2P_Cfg2_SW_Ver_Byte11_29 "DCDC软件版本号Byte11对应ASCII码";
CM_ SG_ 2499931741 D2P_Cfg2_SW_Ver_Byte12_29 "DCDC软件版本号Byte12对应ASCII码";
CM_ SG_ 2499931741 D2P_Cfg2_SW_Ver_Byte13_29 "DCDC软件版本号Byte13对应ASCII码";
CM_ SG_ 2499931741 D2P_Cfg2_SW_Ver_Byte14_29 "DCDC软件版本号Byte14对应ASCII码";
CM_ SG_ 2499931741 D2P_Cfg2_SW_Ver_Byte15_29 "DCDC软件版本号最高字节Byte15对应ASCII码";
CM_ SG_ 2499931742 D2P_Cfg2_SW_Ver_Byte8_30 "DCDC软件版本号Byte8对应ASCII码";
CM_ SG_ 2499931742 D2P_Cfg2_SW_Ver_Byte9_30 "DCDC软件版本号Byte9对应ASCII码";
CM_ SG_ 2499931742 D2P_Cfg2_SW_Ver_Byte10_30 "DCDC软件版本号Byte10对应ASCII码";
CM_ SG_ 2499931742 D2P_Cfg2_SW_Ver_Byte11_30 "DCDC软件版本号Byte11对应ASCII码";
CM_ SG_ 2499931742 D2P_Cfg2_SW_Ver_Byte12_30 "DCDC软件版本号Byte12对应ASCII码";
CM_ SG_ 2499931742 D2P_Cfg2_SW_Ver_Byte13_30 "DCDC软件版本号Byte13对应ASCII码";
CM_ SG_ 2499931742 D2P_Cfg2_SW_Ver_Byte14_30 "DCDC软件版本号Byte14对应ASCII码";
CM_ SG_ 2499931742 D2P_Cfg2_SW_Ver_Byte15_30 "DCDC软件版本号最高字节Byte15对应ASCII码";
CM_ SG_ 2499931743 D2P_Cfg2_SW_Ver_Byte8_31 "DCDC软件版本号Byte8对应ASCII码";
CM_ SG_ 2499931743 D2P_Cfg2_SW_Ver_Byte9_31 "DCDC软件版本号Byte9对应ASCII码";
CM_ SG_ 2499931743 D2P_Cfg2_SW_Ver_Byte10_31 "DCDC软件版本号Byte10对应ASCII码";
CM_ SG_ 2499931743 D2P_Cfg2_SW_Ver_Byte11_31 "DCDC软件版本号Byte11对应ASCII码";
CM_ SG_ 2499931743 D2P_Cfg2_SW_Ver_Byte12_31 "DCDC软件版本号Byte12对应ASCII码";
CM_ SG_ 2499931743 D2P_Cfg2_SW_Ver_Byte13_31 "DCDC软件版本号Byte13对应ASCII码";
CM_ SG_ 2499931743 D2P_Cfg2_SW_Ver_Byte14_31 "DCDC软件版本号Byte14对应ASCII码";
CM_ SG_ 2499931743 D2P_Cfg2_SW_Ver_Byte15_31 "DCDC软件版本号最高字节Byte15对应ASCII码";
CM_ SG_ 2499931744 D2P_Cfg2_SW_Ver_Byte8_32 "DCDC软件版本号Byte8对应ASCII码";
CM_ SG_ 2499931744 D2P_Cfg2_SW_Ver_Byte9_32 "DCDC软件版本号Byte9对应ASCII码";
CM_ SG_ 2499931744 D2P_Cfg2_SW_Ver_Byte10_32 "DCDC软件版本号Byte10对应ASCII码";
CM_ SG_ 2499931744 D2P_Cfg2_SW_Ver_Byte11_32 "DCDC软件版本号Byte11对应ASCII码";
CM_ SG_ 2499931744 D2P_Cfg2_SW_Ver_Byte12_32 "DCDC软件版本号Byte12对应ASCII码";
CM_ SG_ 2499931744 D2P_Cfg2_SW_Ver_Byte13_32 "DCDC软件版本号Byte13对应ASCII码";
CM_ SG_ 2499931744 D2P_Cfg2_SW_Ver_Byte14_32 "DCDC软件版本号Byte14对应ASCII码";
CM_ SG_ 2499931744 D2P_Cfg2_SW_Ver_Byte15_32 "DCDC软件版本号最高字节Byte15对应ASCII码";
CM_ SG_ 2499931745 D2P_Cfg2_SW_Ver_Byte8_33 "DCDC软件版本号Byte8对应ASCII码";
CM_ SG_ 2499931745 D2P_Cfg2_SW_Ver_Byte9_33 "DCDC软件版本号Byte9对应ASCII码";
CM_ SG_ 2499931745 D2P_Cfg2_SW_Ver_Byte10_33 "DCDC软件版本号Byte10对应ASCII码";
CM_ SG_ 2499931745 D2P_Cfg2_SW_Ver_Byte11_33 "DCDC软件版本号Byte11对应ASCII码";
CM_ SG_ 2499931745 D2P_Cfg2_SW_Ver_Byte12_33 "DCDC软件版本号Byte12对应ASCII码";
CM_ SG_ 2499931745 D2P_Cfg2_SW_Ver_Byte13_33 "DCDC软件版本号Byte13对应ASCII码";
CM_ SG_ 2499931745 D2P_Cfg2_SW_Ver_Byte14_33 "DCDC软件版本号Byte14对应ASCII码";
CM_ SG_ 2499931745 D2P_Cfg2_SW_Ver_Byte15_33 "DCDC软件版本号最高字节Byte15对应ASCII码";
CM_ SG_ 2499931746 D2P_Cfg2_SW_Ver_Byte8_34 "DCDC软件版本号Byte8对应ASCII码";
CM_ SG_ 2499931746 D2P_Cfg2_SW_Ver_Byte9_34 "DCDC软件版本号Byte9对应ASCII码";
CM_ SG_ 2499931746 D2P_Cfg2_SW_Ver_Byte10_34 "DCDC软件版本号Byte10对应ASCII码";
CM_ SG_ 2499931746 D2P_Cfg2_SW_Ver_Byte11_34 "DCDC软件版本号Byte11对应ASCII码";
CM_ SG_ 2499931746 D2P_Cfg2_SW_Ver_Byte12_34 "DCDC软件版本号Byte12对应ASCII码";
CM_ SG_ 2499931746 D2P_Cfg2_SW_Ver_Byte13_34 "DCDC软件版本号Byte13对应ASCII码";
CM_ SG_ 2499931746 D2P_Cfg2_SW_Ver_Byte14_34 "DCDC软件版本号Byte14对应ASCII码";
CM_ SG_ 2499931746 D2P_Cfg2_SW_Ver_Byte15_34 "DCDC软件版本号最高字节Byte15对应ASCII码";
CM_ SG_ 2499931747 D2P_Cfg2_SW_Ver_Byte8_35 "DCDC软件版本号Byte8对应ASCII码";
CM_ SG_ 2499931747 D2P_Cfg2_SW_Ver_Byte9_35 "DCDC软件版本号Byte9对应ASCII码";
CM_ SG_ 2499931747 D2P_Cfg2_SW_Ver_Byte10_35 "DCDC软件版本号Byte10对应ASCII码";
CM_ SG_ 2499931747 D2P_Cfg2_SW_Ver_Byte11_35 "DCDC软件版本号Byte11对应ASCII码";
CM_ SG_ 2499931747 D2P_Cfg2_SW_Ver_Byte12_35 "DCDC软件版本号Byte12对应ASCII码";
CM_ SG_ 2499931747 D2P_Cfg2_SW_Ver_Byte13_35 "DCDC软件版本号Byte13对应ASCII码";
CM_ SG_ 2499931747 D2P_Cfg2_SW_Ver_Byte14_35 "DCDC软件版本号Byte14对应ASCII码";
CM_ SG_ 2499931747 D2P_Cfg2_SW_Ver_Byte15_35 "DCDC软件版本号最高字节Byte15对应ASCII码";
CM_ SG_ 2499931748 D2P_Cfg2_SW_Ver_Byte8_36 "DCDC软件版本号Byte8对应ASCII码";
CM_ SG_ 2499931748 D2P_Cfg2_SW_Ver_Byte9_36 "DCDC软件版本号Byte9对应ASCII码";
CM_ SG_ 2499931748 D2P_Cfg2_SW_Ver_Byte10_36 "DCDC软件版本号Byte10对应ASCII码";
CM_ SG_ 2499931748 D2P_Cfg2_SW_Ver_Byte11_36 "DCDC软件版本号Byte11对应ASCII码";
CM_ SG_ 2499931748 D2P_Cfg2_SW_Ver_Byte12_36 "DCDC软件版本号Byte12对应ASCII码";
CM_ SG_ 2499931748 D2P_Cfg2_SW_Ver_Byte13_36 "DCDC软件版本号Byte13对应ASCII码";
CM_ SG_ 2499931748 D2P_Cfg2_SW_Ver_Byte14_36 "DCDC软件版本号Byte14对应ASCII码";
CM_ SG_ 2499931748 D2P_Cfg2_SW_Ver_Byte15_36 "DCDC软件版本号最高字节Byte15对应ASCII码";
CM_ SG_ 2499931749 D2P_Cfg2_SW_Ver_Byte8_37 "DCDC软件版本号Byte8对应ASCII码";
CM_ SG_ 2499931749 D2P_Cfg2_SW_Ver_Byte9_37 "DCDC软件版本号Byte9对应ASCII码";
CM_ SG_ 2499931749 D2P_Cfg2_SW_Ver_Byte10_37 "DCDC软件版本号Byte10对应ASCII码";
CM_ SG_ 2499931749 D2P_Cfg2_SW_Ver_Byte11_37 "DCDC软件版本号Byte11对应ASCII码";
CM_ SG_ 2499931749 D2P_Cfg2_SW_Ver_Byte12_37 "DCDC软件版本号Byte12对应ASCII码";
CM_ SG_ 2499931749 D2P_Cfg2_SW_Ver_Byte13_37 "DCDC软件版本号Byte13对应ASCII码";
CM_ SG_ 2499931749 D2P_Cfg2_SW_Ver_Byte14_37 "DCDC软件版本号Byte14对应ASCII码";
CM_ SG_ 2499931749 D2P_Cfg2_SW_Ver_Byte15_37 "DCDC软件版本号最高字节Byte15对应ASCII码";
CM_ SG_ 2499931750 D2P_Cfg2_SW_Ver_Byte8_38 "DCDC软件版本号Byte8对应ASCII码";
CM_ SG_ 2499931750 D2P_Cfg2_SW_Ver_Byte9_38 "DCDC软件版本号Byte9对应ASCII码";
CM_ SG_ 2499931750 D2P_Cfg2_SW_Ver_Byte10_38 "DCDC软件版本号Byte10对应ASCII码";
CM_ SG_ 2499931750 D2P_Cfg2_SW_Ver_Byte11_38 "DCDC软件版本号Byte11对应ASCII码";
CM_ SG_ 2499931750 D2P_Cfg2_SW_Ver_Byte12_38 "DCDC软件版本号Byte12对应ASCII码";
CM_ SG_ 2499931750 D2P_Cfg2_SW_Ver_Byte13_38 "DCDC软件版本号Byte13对应ASCII码";
CM_ SG_ 2499931750 D2P_Cfg2_SW_Ver_Byte14_38 "DCDC软件版本号Byte14对应ASCII码";
CM_ SG_ 2499931750 D2P_Cfg2_SW_Ver_Byte15_38 "DCDC软件版本号最高字节Byte15对应ASCII码";
CM_ SG_ 2499931751 D2P_Cfg2_SW_Ver_Byte8_39 "DCDC软件版本号Byte8对应ASCII码";
CM_ SG_ 2499931751 D2P_Cfg2_SW_Ver_Byte9_39 "DCDC软件版本号Byte9对应ASCII码";
CM_ SG_ 2499931751 D2P_Cfg2_SW_Ver_Byte10_39 "DCDC软件版本号Byte10对应ASCII码";
CM_ SG_ 2499931751 D2P_Cfg2_SW_Ver_Byte11_39 "DCDC软件版本号Byte11对应ASCII码";
CM_ SG_ 2499931751 D2P_Cfg2_SW_Ver_Byte12_39 "DCDC软件版本号Byte12对应ASCII码";
CM_ SG_ 2499931751 D2P_Cfg2_SW_Ver_Byte13_39 "DCDC软件版本号Byte13对应ASCII码";
CM_ SG_ 2499931751 D2P_Cfg2_SW_Ver_Byte14_39 "DCDC软件版本号Byte14对应ASCII码";
CM_ SG_ 2499931751 D2P_Cfg2_SW_Ver_Byte15_39 "DCDC软件版本号最高字节Byte15对应ASCII码";
CM_ SG_ 2499931752 D2P_Cfg2_SW_Ver_Byte8_40 "DCDC软件版本号Byte8对应ASCII码";
CM_ SG_ 2499931752 D2P_Cfg2_SW_Ver_Byte9_40 "DCDC软件版本号Byte9对应ASCII码";
CM_ SG_ 2499931752 D2P_Cfg2_SW_Ver_Byte10_40 "DCDC软件版本号Byte10对应ASCII码";
CM_ SG_ 2499931752 D2P_Cfg2_SW_Ver_Byte11_40 "DCDC软件版本号Byte11对应ASCII码";
CM_ SG_ 2499931752 D2P_Cfg2_SW_Ver_Byte12_40 "DCDC软件版本号Byte12对应ASCII码";
CM_ SG_ 2499931752 D2P_Cfg2_SW_Ver_Byte13_40 "DCDC软件版本号Byte13对应ASCII码";
CM_ SG_ 2499931752 D2P_Cfg2_SW_Ver_Byte14_40 "DCDC软件版本号Byte14对应ASCII码";
CM_ SG_ 2499931752 D2P_Cfg2_SW_Ver_Byte15_40 "DCDC软件版本号最高字节Byte15对应ASCII码";
CM_ SG_ 2499931753 D2P_Cfg2_SW_Ver_Byte8_41 "DCDC软件版本号Byte8对应ASCII码";
CM_ SG_ 2499931753 D2P_Cfg2_SW_Ver_Byte9_41 "DCDC软件版本号Byte9对应ASCII码";
CM_ SG_ 2499931753 D2P_Cfg2_SW_Ver_Byte10_41 "DCDC软件版本号Byte10对应ASCII码";
CM_ SG_ 2499931753 D2P_Cfg2_SW_Ver_Byte11_41 "DCDC软件版本号Byte11对应ASCII码";
CM_ SG_ 2499931753 D2P_Cfg2_SW_Ver_Byte12_41 "DCDC软件版本号Byte12对应ASCII码";
CM_ SG_ 2499931753 D2P_Cfg2_SW_Ver_Byte13_41 "DCDC软件版本号Byte13对应ASCII码";
CM_ SG_ 2499931753 D2P_Cfg2_SW_Ver_Byte14_41 "DCDC软件版本号Byte14对应ASCII码";
CM_ SG_ 2499931753 D2P_Cfg2_SW_Ver_Byte15_41 "DCDC软件版本号最高字节Byte15对应ASCII码";
CM_ SG_ 2499931754 D2P_Cfg2_SW_Ver_Byte8_42 "DCDC软件版本号Byte8对应ASCII码";
CM_ SG_ 2499931754 D2P_Cfg2_SW_Ver_Byte9_42 "DCDC软件版本号Byte9对应ASCII码";
CM_ SG_ 2499931754 D2P_Cfg2_SW_Ver_Byte10_42 "DCDC软件版本号Byte10对应ASCII码";
CM_ SG_ 2499931754 D2P_Cfg2_SW_Ver_Byte11_42 "DCDC软件版本号Byte11对应ASCII码";
CM_ SG_ 2499931754 D2P_Cfg2_SW_Ver_Byte12_42 "DCDC软件版本号Byte12对应ASCII码";
CM_ SG_ 2499931754 D2P_Cfg2_SW_Ver_Byte13_42 "DCDC软件版本号Byte13对应ASCII码";
CM_ SG_ 2499931754 D2P_Cfg2_SW_Ver_Byte14_42 "DCDC软件版本号Byte14对应ASCII码";
CM_ SG_ 2499931754 D2P_Cfg2_SW_Ver_Byte15_42 "DCDC软件版本号最高字节Byte15对应ASCII码";
CM_ SG_ 2499931755 D2P_Cfg2_SW_Ver_Byte8_43 "DCDC软件版本号Byte8对应ASCII码";
CM_ SG_ 2499931755 D2P_Cfg2_SW_Ver_Byte9_43 "DCDC软件版本号Byte9对应ASCII码";
CM_ SG_ 2499931755 D2P_Cfg2_SW_Ver_Byte10_43 "DCDC软件版本号Byte10对应ASCII码";
CM_ SG_ 2499931755 D2P_Cfg2_SW_Ver_Byte11_43 "DCDC软件版本号Byte11对应ASCII码";
CM_ SG_ 2499931755 D2P_Cfg2_SW_Ver_Byte12_43 "DCDC软件版本号Byte12对应ASCII码";
CM_ SG_ 2499931755 D2P_Cfg2_SW_Ver_Byte13_43 "DCDC软件版本号Byte13对应ASCII码";
CM_ SG_ 2499931755 D2P_Cfg2_SW_Ver_Byte14_43 "DCDC软件版本号Byte14对应ASCII码";
CM_ SG_ 2499931755 D2P_Cfg2_SW_Ver_Byte15_43 "DCDC软件版本号最高字节Byte15对应ASCII码";
CM_ SG_ 2499931756 D2P_Cfg2_SW_Ver_Byte8_44 "DCDC软件版本号Byte8对应ASCII码";
CM_ SG_ 2499931756 D2P_Cfg2_SW_Ver_Byte9_44 "DCDC软件版本号Byte9对应ASCII码";
CM_ SG_ 2499931756 D2P_Cfg2_SW_Ver_Byte10_44 "DCDC软件版本号Byte10对应ASCII码";
CM_ SG_ 2499931756 D2P_Cfg2_SW_Ver_Byte11_44 "DCDC软件版本号Byte11对应ASCII码";
CM_ SG_ 2499931756 D2P_Cfg2_SW_Ver_Byte12_44 "DCDC软件版本号Byte12对应ASCII码";
CM_ SG_ 2499931756 D2P_Cfg2_SW_Ver_Byte13_44 "DCDC软件版本号Byte13对应ASCII码";
CM_ SG_ 2499931756 D2P_Cfg2_SW_Ver_Byte14_44 "DCDC软件版本号Byte14对应ASCII码";
CM_ SG_ 2499931756 D2P_Cfg2_SW_Ver_Byte15_44 "DCDC软件版本号最高字节Byte15对应ASCII码";
CM_ SG_ 2499931757 D2P_Cfg2_SW_Ver_Byte8_45 "DCDC软件版本号Byte8对应ASCII码";
CM_ SG_ 2499931757 D2P_Cfg2_SW_Ver_Byte9_45 "DCDC软件版本号Byte9对应ASCII码";
CM_ SG_ 2499931757 D2P_Cfg2_SW_Ver_Byte10_45 "DCDC软件版本号Byte10对应ASCII码";
CM_ SG_ 2499931757 D2P_Cfg2_SW_Ver_Byte11_45 "DCDC软件版本号Byte11对应ASCII码";
CM_ SG_ 2499931757 D2P_Cfg2_SW_Ver_Byte12_45 "DCDC软件版本号Byte12对应ASCII码";
CM_ SG_ 2499931757 D2P_Cfg2_SW_Ver_Byte13_45 "DCDC软件版本号Byte13对应ASCII码";
CM_ SG_ 2499931757 D2P_Cfg2_SW_Ver_Byte14_45 "DCDC软件版本号Byte14对应ASCII码";
CM_ SG_ 2499931757 D2P_Cfg2_SW_Ver_Byte15_45 "DCDC软件版本号最高字节Byte15对应ASCII码";
CM_ SG_ 2499931758 D2P_Cfg2_SW_Ver_Byte8_46 "DCDC软件版本号Byte8对应ASCII码";
CM_ SG_ 2499931758 D2P_Cfg2_SW_Ver_Byte9_46 "DCDC软件版本号Byte9对应ASCII码";
CM_ SG_ 2499931758 D2P_Cfg2_SW_Ver_Byte10_46 "DCDC软件版本号Byte10对应ASCII码";
CM_ SG_ 2499931758 D2P_Cfg2_SW_Ver_Byte11_46 "DCDC软件版本号Byte11对应ASCII码";
CM_ SG_ 2499931758 D2P_Cfg2_SW_Ver_Byte12_46 "DCDC软件版本号Byte12对应ASCII码";
CM_ SG_ 2499931758 D2P_Cfg2_SW_Ver_Byte13_46 "DCDC软件版本号Byte13对应ASCII码";
CM_ SG_ 2499931758 D2P_Cfg2_SW_Ver_Byte14_46 "DCDC软件版本号Byte14对应ASCII码";
CM_ SG_ 2499931758 D2P_Cfg2_SW_Ver_Byte15_46 "DCDC软件版本号最高字节Byte15对应ASCII码";
CM_ SG_ 2499931759 D2P_Cfg2_SW_Ver_Byte8_47 "DCDC软件版本号Byte8对应ASCII码";
CM_ SG_ 2499931759 D2P_Cfg2_SW_Ver_Byte9_47 "DCDC软件版本号Byte9对应ASCII码";
CM_ SG_ 2499931759 D2P_Cfg2_SW_Ver_Byte10_47 "DCDC软件版本号Byte10对应ASCII码";
CM_ SG_ 2499931759 D2P_Cfg2_SW_Ver_Byte11_47 "DCDC软件版本号Byte11对应ASCII码";
CM_ SG_ 2499931759 D2P_Cfg2_SW_Ver_Byte12_47 "DCDC软件版本号Byte12对应ASCII码";
CM_ SG_ 2499931759 D2P_Cfg2_SW_Ver_Byte13_47 "DCDC软件版本号Byte13对应ASCII码";
CM_ SG_ 2499931759 D2P_Cfg2_SW_Ver_Byte14_47 "DCDC软件版本号Byte14对应ASCII码";
CM_ SG_ 2499931759 D2P_Cfg2_SW_Ver_Byte15_47 "DCDC软件版本号最高字节Byte15对应ASCII码";
CM_ SG_ 2499931760 D2P_Cfg2_SW_Ver_Byte8_48 "DCDC软件版本号Byte8对应ASCII码";
CM_ SG_ 2499931760 D2P_Cfg2_SW_Ver_Byte9_48 "DCDC软件版本号Byte9对应ASCII码";
CM_ SG_ 2499931760 D2P_Cfg2_SW_Ver_Byte10_48 "DCDC软件版本号Byte10对应ASCII码";
CM_ SG_ 2499931760 D2P_Cfg2_SW_Ver_Byte11_48 "DCDC软件版本号Byte11对应ASCII码";
CM_ SG_ 2499931760 D2P_Cfg2_SW_Ver_Byte12_48 "DCDC软件版本号Byte12对应ASCII码";
CM_ SG_ 2499931760 D2P_Cfg2_SW_Ver_Byte13_48 "DCDC软件版本号Byte13对应ASCII码";
CM_ SG_ 2499931760 D2P_Cfg2_SW_Ver_Byte14_48 "DCDC软件版本号Byte14对应ASCII码";
CM_ SG_ 2499931760 D2P_Cfg2_SW_Ver_Byte15_48 "DCDC软件版本号最高字节Byte15对应ASCII码";
CM_ SG_ 2499931761 D2P_Cfg2_SW_Ver_Byte8_49 "DCDC软件版本号Byte8对应ASCII码";
CM_ SG_ 2499931761 D2P_Cfg2_SW_Ver_Byte9_49 "DCDC软件版本号Byte9对应ASCII码";
CM_ SG_ 2499931761 D2P_Cfg2_SW_Ver_Byte10_49 "DCDC软件版本号Byte10对应ASCII码";
CM_ SG_ 2499931761 D2P_Cfg2_SW_Ver_Byte11_49 "DCDC软件版本号Byte11对应ASCII码";
CM_ SG_ 2499931761 D2P_Cfg2_SW_Ver_Byte12_49 "DCDC软件版本号Byte12对应ASCII码";
CM_ SG_ 2499931761 D2P_Cfg2_SW_Ver_Byte13_49 "DCDC软件版本号Byte13对应ASCII码";
CM_ SG_ 2499931761 D2P_Cfg2_SW_Ver_Byte14_49 "DCDC软件版本号Byte14对应ASCII码";
CM_ SG_ 2499931761 D2P_Cfg2_SW_Ver_Byte15_49 "DCDC软件版本号最高字节Byte15对应ASCII码";
CM_ SG_ 2499931762 D2P_Cfg2_SW_Ver_Byte8_50 "DCDC软件版本号Byte8对应ASCII码";
CM_ SG_ 2499931762 D2P_Cfg2_SW_Ver_Byte9_50 "DCDC软件版本号Byte9对应ASCII码";
CM_ SG_ 2499931762 D2P_Cfg2_SW_Ver_Byte10_50 "DCDC软件版本号Byte10对应ASCII码";
CM_ SG_ 2499931762 D2P_Cfg2_SW_Ver_Byte11_50 "DCDC软件版本号Byte11对应ASCII码";
CM_ SG_ 2499931762 D2P_Cfg2_SW_Ver_Byte12_50 "DCDC软件版本号Byte12对应ASCII码";
CM_ SG_ 2499931762 D2P_Cfg2_SW_Ver_Byte13_50 "DCDC软件版本号Byte13对应ASCII码";
CM_ SG_ 2499931762 D2P_Cfg2_SW_Ver_Byte14_50 "DCDC软件版本号Byte14对应ASCII码";
CM_ SG_ 2499931762 D2P_Cfg2_SW_Ver_Byte15_50 "DCDC软件版本号最高字节Byte15对应ASCII码";
CM_ SG_ 2499931763 D2P_Cfg2_SW_Ver_Byte8_51 "DCDC软件版本号Byte8对应ASCII码";
CM_ SG_ 2499931763 D2P_Cfg2_SW_Ver_Byte9_51 "DCDC软件版本号Byte9对应ASCII码";
CM_ SG_ 2499931763 D2P_Cfg2_SW_Ver_Byte10_51 "DCDC软件版本号Byte10对应ASCII码";
CM_ SG_ 2499931763 D2P_Cfg2_SW_Ver_Byte11_51 "DCDC软件版本号Byte11对应ASCII码";
CM_ SG_ 2499931763 D2P_Cfg2_SW_Ver_Byte12_51 "DCDC软件版本号Byte12对应ASCII码";
CM_ SG_ 2499931763 D2P_Cfg2_SW_Ver_Byte13_51 "DCDC软件版本号Byte13对应ASCII码";
CM_ SG_ 2499931763 D2P_Cfg2_SW_Ver_Byte14_51 "DCDC软件版本号Byte14对应ASCII码";
CM_ SG_ 2499931763 D2P_Cfg2_SW_Ver_Byte15_51 "DCDC软件版本号最高字节Byte15对应ASCII码";
CM_ SG_ 2499931764 D2P_Cfg2_SW_Ver_Byte8_52 "DCDC软件版本号Byte8对应ASCII码";
CM_ SG_ 2499931764 D2P_Cfg2_SW_Ver_Byte9_52 "DCDC软件版本号Byte9对应ASCII码";
CM_ SG_ 2499931764 D2P_Cfg2_SW_Ver_Byte10_52 "DCDC软件版本号Byte10对应ASCII码";
CM_ SG_ 2499931764 D2P_Cfg2_SW_Ver_Byte11_52 "DCDC软件版本号Byte11对应ASCII码";
CM_ SG_ 2499931764 D2P_Cfg2_SW_Ver_Byte12_52 "DCDC软件版本号Byte12对应ASCII码";
CM_ SG_ 2499931764 D2P_Cfg2_SW_Ver_Byte13_52 "DCDC软件版本号Byte13对应ASCII码";
CM_ SG_ 2499931764 D2P_Cfg2_SW_Ver_Byte14_52 "DCDC软件版本号Byte14对应ASCII码";
CM_ SG_ 2499931764 D2P_Cfg2_SW_Ver_Byte15_52 "DCDC软件版本号最高字节Byte15对应ASCII码";
CM_ SG_ 2499931765 D2P_Cfg2_SW_Ver_Byte8_53 "DCDC软件版本号Byte8对应ASCII码";
CM_ SG_ 2499931765 D2P_Cfg2_SW_Ver_Byte9_53 "DCDC软件版本号Byte9对应ASCII码";
CM_ SG_ 2499931765 D2P_Cfg2_SW_Ver_Byte10_53 "DCDC软件版本号Byte10对应ASCII码";
CM_ SG_ 2499931765 D2P_Cfg2_SW_Ver_Byte11_53 "DCDC软件版本号Byte11对应ASCII码";
CM_ SG_ 2499931765 D2P_Cfg2_SW_Ver_Byte12_53 "DCDC软件版本号Byte12对应ASCII码";
CM_ SG_ 2499931765 D2P_Cfg2_SW_Ver_Byte13_53 "DCDC软件版本号Byte13对应ASCII码";
CM_ SG_ 2499931765 D2P_Cfg2_SW_Ver_Byte14_53 "DCDC软件版本号Byte14对应ASCII码";
CM_ SG_ 2499931765 D2P_Cfg2_SW_Ver_Byte15_53 "DCDC软件版本号最高字节Byte15对应ASCII码";
CM_ SG_ 2499931766 D2P_Cfg2_SW_Ver_Byte8_54 "DCDC软件版本号Byte8对应ASCII码";
CM_ SG_ 2499931766 D2P_Cfg2_SW_Ver_Byte9_54 "DCDC软件版本号Byte9对应ASCII码";
CM_ SG_ 2499931766 D2P_Cfg2_SW_Ver_Byte10_54 "DCDC软件版本号Byte10对应ASCII码";
CM_ SG_ 2499931766 D2P_Cfg2_SW_Ver_Byte11_54 "DCDC软件版本号Byte11对应ASCII码";
CM_ SG_ 2499931766 D2P_Cfg2_SW_Ver_Byte12_54 "DCDC软件版本号Byte12对应ASCII码";
CM_ SG_ 2499931766 D2P_Cfg2_SW_Ver_Byte13_54 "DCDC软件版本号Byte13对应ASCII码";
CM_ SG_ 2499931766 D2P_Cfg2_SW_Ver_Byte14_54 "DCDC软件版本号Byte14对应ASCII码";
CM_ SG_ 2499931766 D2P_Cfg2_SW_Ver_Byte15_54 "DCDC软件版本号最高字节Byte15对应ASCII码";
CM_ SG_ 2499931767 D2P_Cfg2_SW_Ver_Byte8_55 "DCDC软件版本号Byte8对应ASCII码";
CM_ SG_ 2499931767 D2P_Cfg2_SW_Ver_Byte9_55 "DCDC软件版本号Byte9对应ASCII码";
CM_ SG_ 2499931767 D2P_Cfg2_SW_Ver_Byte10_55 "DCDC软件版本号Byte10对应ASCII码";
CM_ SG_ 2499931767 D2P_Cfg2_SW_Ver_Byte11_55 "DCDC软件版本号Byte11对应ASCII码";
CM_ SG_ 2499931767 D2P_Cfg2_SW_Ver_Byte12_55 "DCDC软件版本号Byte12对应ASCII码";
CM_ SG_ 2499931767 D2P_Cfg2_SW_Ver_Byte13_55 "DCDC软件版本号Byte13对应ASCII码";
CM_ SG_ 2499931767 D2P_Cfg2_SW_Ver_Byte14_55 "DCDC软件版本号Byte14对应ASCII码";
CM_ SG_ 2499931767 D2P_Cfg2_SW_Ver_Byte15_55 "DCDC软件版本号最高字节Byte15对应ASCII码";
CM_ SG_ 2499931768 D2P_Cfg2_SW_Ver_Byte8_56 "DCDC软件版本号Byte8对应ASCII码";
CM_ SG_ 2499931768 D2P_Cfg2_SW_Ver_Byte9_56 "DCDC软件版本号Byte9对应ASCII码";
CM_ SG_ 2499931768 D2P_Cfg2_SW_Ver_Byte10_56 "DCDC软件版本号Byte10对应ASCII码";
CM_ SG_ 2499931768 D2P_Cfg2_SW_Ver_Byte11_56 "DCDC软件版本号Byte11对应ASCII码";
CM_ SG_ 2499931768 D2P_Cfg2_SW_Ver_Byte12_56 "DCDC软件版本号Byte12对应ASCII码";
CM_ SG_ 2499931768 D2P_Cfg2_SW_Ver_Byte13_56 "DCDC软件版本号Byte13对应ASCII码";
CM_ SG_ 2499931768 D2P_Cfg2_SW_Ver_Byte14_56 "DCDC软件版本号Byte14对应ASCII码";
CM_ SG_ 2499931768 D2P_Cfg2_SW_Ver_Byte15_56 "DCDC软件版本号最高字节Byte15对应ASCII码";
CM_ SG_ 2499931769 D2P_Cfg2_SW_Ver_Byte8_57 "DCDC软件版本号Byte8对应ASCII码";
CM_ SG_ 2499931769 D2P_Cfg2_SW_Ver_Byte9_57 "DCDC软件版本号Byte9对应ASCII码";
CM_ SG_ 2499931769 D2P_Cfg2_SW_Ver_Byte10_57 "DCDC软件版本号Byte10对应ASCII码";
CM_ SG_ 2499931769 D2P_Cfg2_SW_Ver_Byte11_57 "DCDC软件版本号Byte11对应ASCII码";
CM_ SG_ 2499931769 D2P_Cfg2_SW_Ver_Byte12_57 "DCDC软件版本号Byte12对应ASCII码";
CM_ SG_ 2499931769 D2P_Cfg2_SW_Ver_Byte13_57 "DCDC软件版本号Byte13对应ASCII码";
CM_ SG_ 2499931769 D2P_Cfg2_SW_Ver_Byte14_57 "DCDC软件版本号Byte14对应ASCII码";
CM_ SG_ 2499931769 D2P_Cfg2_SW_Ver_Byte15_57 "DCDC软件版本号最高字节Byte15对应ASCII码";
CM_ SG_ 2499931770 D2P_Cfg2_SW_Ver_Byte8_58 "DCDC软件版本号Byte8对应ASCII码";
CM_ SG_ 2499931770 D2P_Cfg2_SW_Ver_Byte9_58 "DCDC软件版本号Byte9对应ASCII码";
CM_ SG_ 2499931770 D2P_Cfg2_SW_Ver_Byte10_58 "DCDC软件版本号Byte10对应ASCII码";
CM_ SG_ 2499931770 D2P_Cfg2_SW_Ver_Byte11_58 "DCDC软件版本号Byte11对应ASCII码";
CM_ SG_ 2499931770 D2P_Cfg2_SW_Ver_Byte12_58 "DCDC软件版本号Byte12对应ASCII码";
CM_ SG_ 2499931770 D2P_Cfg2_SW_Ver_Byte13_58 "DCDC软件版本号Byte13对应ASCII码";
CM_ SG_ 2499931770 D2P_Cfg2_SW_Ver_Byte14_58 "DCDC软件版本号Byte14对应ASCII码";
CM_ SG_ 2499931770 D2P_Cfg2_SW_Ver_Byte15_58 "DCDC软件版本号最高字节Byte15对应ASCII码";
CM_ SG_ 2499931771 D2P_Cfg2_SW_Ver_Byte8_59 "DCDC软件版本号Byte8对应ASCII码";
CM_ SG_ 2499931771 D2P_Cfg2_SW_Ver_Byte9_59 "DCDC软件版本号Byte9对应ASCII码";
CM_ SG_ 2499931771 D2P_Cfg2_SW_Ver_Byte10_59 "DCDC软件版本号Byte10对应ASCII码";
CM_ SG_ 2499931771 D2P_Cfg2_SW_Ver_Byte11_59 "DCDC软件版本号Byte11对应ASCII码";
CM_ SG_ 2499931771 D2P_Cfg2_SW_Ver_Byte12_59 "DCDC软件版本号Byte12对应ASCII码";
CM_ SG_ 2499931771 D2P_Cfg2_SW_Ver_Byte13_59 "DCDC软件版本号Byte13对应ASCII码";
CM_ SG_ 2499931771 D2P_Cfg2_SW_Ver_Byte14_59 "DCDC软件版本号Byte14对应ASCII码";
CM_ SG_ 2499931771 D2P_Cfg2_SW_Ver_Byte15_59 "DCDC软件版本号最高字节Byte15对应ASCII码";
CM_ SG_ 2499931772 D2P_Cfg2_SW_Ver_Byte8_60 "DCDC软件版本号Byte8对应ASCII码";
CM_ SG_ 2499931772 D2P_Cfg2_SW_Ver_Byte9_60 "DCDC软件版本号Byte9对应ASCII码";
CM_ SG_ 2499931772 D2P_Cfg2_SW_Ver_Byte10_60 "DCDC软件版本号Byte10对应ASCII码";
CM_ SG_ 2499931772 D2P_Cfg2_SW_Ver_Byte11_60 "DCDC软件版本号Byte11对应ASCII码";
CM_ SG_ 2499931772 D2P_Cfg2_SW_Ver_Byte12_60 "DCDC软件版本号Byte12对应ASCII码";
CM_ SG_ 2499931772 D2P_Cfg2_SW_Ver_Byte13_60 "DCDC软件版本号Byte13对应ASCII码";
CM_ SG_ 2499931772 D2P_Cfg2_SW_Ver_Byte14_60 "DCDC软件版本号Byte14对应ASCII码";
CM_ SG_ 2499931772 D2P_Cfg2_SW_Ver_Byte15_60 "DCDC软件版本号最高字节Byte15对应ASCII码";
CM_ SG_ 2499931773 D2P_Cfg2_SW_Ver_Byte8_61 "DCDC软件版本号Byte8对应ASCII码";
CM_ SG_ 2499931773 D2P_Cfg2_SW_Ver_Byte9_61 "DCDC软件版本号Byte9对应ASCII码";
CM_ SG_ 2499931773 D2P_Cfg2_SW_Ver_Byte10_61 "DCDC软件版本号Byte10对应ASCII码";
CM_ SG_ 2499931773 D2P_Cfg2_SW_Ver_Byte11_61 "DCDC软件版本号Byte11对应ASCII码";
CM_ SG_ 2499931773 D2P_Cfg2_SW_Ver_Byte12_61 "DCDC软件版本号Byte12对应ASCII码";
CM_ SG_ 2499931773 D2P_Cfg2_SW_Ver_Byte13_61 "DCDC软件版本号Byte13对应ASCII码";
CM_ SG_ 2499931773 D2P_Cfg2_SW_Ver_Byte14_61 "DCDC软件版本号Byte14对应ASCII码";
CM_ SG_ 2499931773 D2P_Cfg2_SW_Ver_Byte15_61 "DCDC软件版本号最高字节Byte15对应ASCII码";
CM_ SG_ 2499931774 D2P_Cfg2_SW_Ver_Byte8_62 "DCDC软件版本号Byte8对应ASCII码";
CM_ SG_ 2499931774 D2P_Cfg2_SW_Ver_Byte9_62 "DCDC软件版本号Byte9对应ASCII码";
CM_ SG_ 2499931774 D2P_Cfg2_SW_Ver_Byte10_62 "DCDC软件版本号Byte10对应ASCII码";
CM_ SG_ 2499931774 D2P_Cfg2_SW_Ver_Byte11_62 "DCDC软件版本号Byte11对应ASCII码";
CM_ SG_ 2499931774 D2P_Cfg2_SW_Ver_Byte12_62 "DCDC软件版本号Byte12对应ASCII码";
CM_ SG_ 2499931774 D2P_Cfg2_SW_Ver_Byte13_62 "DCDC软件版本号Byte13对应ASCII码";
CM_ SG_ 2499931774 D2P_Cfg2_SW_Ver_Byte14_62 "DCDC软件版本号Byte14对应ASCII码";
CM_ SG_ 2499931774 D2P_Cfg2_SW_Ver_Byte15_62 "DCDC软件版本号最高字节Byte15对应ASCII码";
CM_ SG_ 2499931775 D2P_Cfg2_SW_Ver_Byte8_63 "DCDC软件版本号Byte8对应ASCII码";
CM_ SG_ 2499931775 D2P_Cfg2_SW_Ver_Byte9_63 "DCDC软件版本号Byte9对应ASCII码";
CM_ SG_ 2499931775 D2P_Cfg2_SW_Ver_Byte10_63 "DCDC软件版本号Byte10对应ASCII码";
CM_ SG_ 2499931775 D2P_Cfg2_SW_Ver_Byte11_63 "DCDC软件版本号Byte11对应ASCII码";
CM_ SG_ 2499931775 D2P_Cfg2_SW_Ver_Byte12_63 "DCDC软件版本号Byte12对应ASCII码";
CM_ SG_ 2499931775 D2P_Cfg2_SW_Ver_Byte13_63 "DCDC软件版本号Byte13对应ASCII码";
CM_ SG_ 2499931775 D2P_Cfg2_SW_Ver_Byte14_63 "DCDC软件版本号Byte14对应ASCII码";
CM_ SG_ 2499931775 D2P_Cfg2_SW_Ver_Byte15_63 "DCDC软件版本号最高字节Byte15对应ASCII码";
CM_ SG_ 2499997249 D2P_Cfg3_HW_Ver_Byte0_01 "DCDC硬件版本号最低字节Byte0对应ASCII码";
CM_ SG_ 2499997249 D2P_Cfg3_HW_Ver_Byte1_01 "DCDC硬件版本号Byte1对应ASCII码";
CM_ SG_ 2499997249 D2P_Cfg3_HW_Ver_Byte2_01 "DCDC硬件版本号Byte2对应ASCII码";
CM_ SG_ 2499997249 D2P_Cfg3_HW_Ver_Byte3_01 "DCDC硬件版本号Byte3对应ASCII码";
CM_ SG_ 2499997249 D2P_Cfg3_HW_Ver_Byte4_01 "DCDC硬件版本号Byte4对应ASCII码";
CM_ SG_ 2499997249 D2P_Cfg3_HW_Ver_Byte5_01 "DCDC硬件版本号Byte5对应ASCII码";
CM_ SG_ 2499997249 D2P_Cfg3_HW_Ver_Byte6_01 "DCDC硬件版本号Byte6对应ASCII码";
CM_ SG_ 2499997249 D2P_Cfg3_HW_Ver_Byte7_01 "DCDC硬件版本号Byte7对应ASCII码";
CM_ SG_ 2499997250 D2P_Cfg3_HW_Ver_Byte0_02 "DCDC硬件版本号最低字节Byte0对应ASCII码";
CM_ SG_ 2499997250 D2P_Cfg3_HW_Ver_Byte1_02 "DCDC硬件版本号Byte1对应ASCII码";
CM_ SG_ 2499997250 D2P_Cfg3_HW_Ver_Byte2_02 "DCDC硬件版本号Byte2对应ASCII码";
CM_ SG_ 2499997250 D2P_Cfg3_HW_Ver_Byte3_02 "DCDC硬件版本号Byte3对应ASCII码";
CM_ SG_ 2499997250 D2P_Cfg3_HW_Ver_Byte4_02 "DCDC硬件版本号Byte4对应ASCII码";
CM_ SG_ 2499997250 D2P_Cfg3_HW_Ver_Byte5_02 "DCDC硬件版本号Byte5对应ASCII码";
CM_ SG_ 2499997250 D2P_Cfg3_HW_Ver_Byte6_02 "DCDC硬件版本号Byte6对应ASCII码";
CM_ SG_ 2499997250 D2P_Cfg3_HW_Ver_Byte7_02 "DCDC硬件版本号Byte7对应ASCII码";
CM_ SG_ 2499997251 D2P_Cfg3_HW_Ver_Byte0_03 "DCDC硬件版本号最低字节Byte0对应ASCII码";
CM_ SG_ 2499997251 D2P_Cfg3_HW_Ver_Byte1_03 "DCDC硬件版本号Byte1对应ASCII码";
CM_ SG_ 2499997251 D2P_Cfg3_HW_Ver_Byte2_03 "DCDC硬件版本号Byte2对应ASCII码";
CM_ SG_ 2499997251 D2P_Cfg3_HW_Ver_Byte3_03 "DCDC硬件版本号Byte3对应ASCII码";
CM_ SG_ 2499997251 D2P_Cfg3_HW_Ver_Byte4_03 "DCDC硬件版本号Byte4对应ASCII码";
CM_ SG_ 2499997251 D2P_Cfg3_HW_Ver_Byte5_03 "DCDC硬件版本号Byte5对应ASCII码";
CM_ SG_ 2499997251 D2P_Cfg3_HW_Ver_Byte6_03 "DCDC硬件版本号Byte6对应ASCII码";
CM_ SG_ 2499997251 D2P_Cfg3_HW_Ver_Byte7_03 "DCDC硬件版本号Byte7对应ASCII码";
CM_ SG_ 2499997252 D2P_Cfg3_HW_Ver_Byte0_04 "DCDC硬件版本号最低字节Byte0对应ASCII码";
CM_ SG_ 2499997252 D2P_Cfg3_HW_Ver_Byte1_04 "DCDC硬件版本号Byte1对应ASCII码";
CM_ SG_ 2499997252 D2P_Cfg3_HW_Ver_Byte2_04 "DCDC硬件版本号Byte2对应ASCII码";
CM_ SG_ 2499997252 D2P_Cfg3_HW_Ver_Byte3_04 "DCDC硬件版本号Byte3对应ASCII码";
CM_ SG_ 2499997252 D2P_Cfg3_HW_Ver_Byte4_04 "DCDC硬件版本号Byte4对应ASCII码";
CM_ SG_ 2499997252 D2P_Cfg3_HW_Ver_Byte5_04 "DCDC硬件版本号Byte5对应ASCII码";
CM_ SG_ 2499997252 D2P_Cfg3_HW_Ver_Byte6_04 "DCDC硬件版本号Byte6对应ASCII码";
CM_ SG_ 2499997252 D2P_Cfg3_HW_Ver_Byte7_04 "DCDC硬件版本号Byte7对应ASCII码";
CM_ SG_ 2499997253 D2P_Cfg3_HW_Ver_Byte0_05 "DCDC硬件版本号最低字节Byte0对应ASCII码";
CM_ SG_ 2499997253 D2P_Cfg3_HW_Ver_Byte1_05 "DCDC硬件版本号Byte1对应ASCII码";
CM_ SG_ 2499997253 D2P_Cfg3_HW_Ver_Byte2_05 "DCDC硬件版本号Byte2对应ASCII码";
CM_ SG_ 2499997253 D2P_Cfg3_HW_Ver_Byte3_05 "DCDC硬件版本号Byte3对应ASCII码";
CM_ SG_ 2499997253 D2P_Cfg3_HW_Ver_Byte4_05 "DCDC硬件版本号Byte4对应ASCII码";
CM_ SG_ 2499997253 D2P_Cfg3_HW_Ver_Byte5_05 "DCDC硬件版本号Byte5对应ASCII码";
CM_ SG_ 2499997253 D2P_Cfg3_HW_Ver_Byte6_05 "DCDC硬件版本号Byte6对应ASCII码";
CM_ SG_ 2499997253 D2P_Cfg3_HW_Ver_Byte7_05 "DCDC硬件版本号Byte7对应ASCII码";
CM_ SG_ 2499997254 D2P_Cfg3_HW_Ver_Byte0_06 "DCDC硬件版本号最低字节Byte0对应ASCII码";
CM_ SG_ 2499997254 D2P_Cfg3_HW_Ver_Byte1_06 "DCDC硬件版本号Byte1对应ASCII码";
CM_ SG_ 2499997254 D2P_Cfg3_HW_Ver_Byte2_06 "DCDC硬件版本号Byte2对应ASCII码";
CM_ SG_ 2499997254 D2P_Cfg3_HW_Ver_Byte3_06 "DCDC硬件版本号Byte3对应ASCII码";
CM_ SG_ 2499997254 D2P_Cfg3_HW_Ver_Byte4_06 "DCDC硬件版本号Byte4对应ASCII码";
CM_ SG_ 2499997254 D2P_Cfg3_HW_Ver_Byte5_06 "DCDC硬件版本号Byte5对应ASCII码";
CM_ SG_ 2499997254 D2P_Cfg3_HW_Ver_Byte6_06 "DCDC硬件版本号Byte6对应ASCII码";
CM_ SG_ 2499997254 D2P_Cfg3_HW_Ver_Byte7_06 "DCDC硬件版本号Byte7对应ASCII码";
CM_ SG_ 2499997255 D2P_Cfg3_HW_Ver_Byte0_07 "DCDC硬件版本号最低字节Byte0对应ASCII码";
CM_ SG_ 2499997255 D2P_Cfg3_HW_Ver_Byte1_07 "DCDC硬件版本号Byte1对应ASCII码";
CM_ SG_ 2499997255 D2P_Cfg3_HW_Ver_Byte2_07 "DCDC硬件版本号Byte2对应ASCII码";
CM_ SG_ 2499997255 D2P_Cfg3_HW_Ver_Byte3_07 "DCDC硬件版本号Byte3对应ASCII码";
CM_ SG_ 2499997255 D2P_Cfg3_HW_Ver_Byte4_07 "DCDC硬件版本号Byte4对应ASCII码";
CM_ SG_ 2499997255 D2P_Cfg3_HW_Ver_Byte5_07 "DCDC硬件版本号Byte5对应ASCII码";
CM_ SG_ 2499997255 D2P_Cfg3_HW_Ver_Byte6_07 "DCDC硬件版本号Byte6对应ASCII码";
CM_ SG_ 2499997255 D2P_Cfg3_HW_Ver_Byte7_07 "DCDC硬件版本号Byte7对应ASCII码";
CM_ SG_ 2499997256 D2P_Cfg3_HW_Ver_Byte0_08 "DCDC硬件版本号最低字节Byte0对应ASCII码";
CM_ SG_ 2499997256 D2P_Cfg3_HW_Ver_Byte1_08 "DCDC硬件版本号Byte1对应ASCII码";
CM_ SG_ 2499997256 D2P_Cfg3_HW_Ver_Byte2_08 "DCDC硬件版本号Byte2对应ASCII码";
CM_ SG_ 2499997256 D2P_Cfg3_HW_Ver_Byte3_08 "DCDC硬件版本号Byte3对应ASCII码";
CM_ SG_ 2499997256 D2P_Cfg3_HW_Ver_Byte4_08 "DCDC硬件版本号Byte4对应ASCII码";
CM_ SG_ 2499997256 D2P_Cfg3_HW_Ver_Byte5_08 "DCDC硬件版本号Byte5对应ASCII码";
CM_ SG_ 2499997256 D2P_Cfg3_HW_Ver_Byte6_08 "DCDC硬件版本号Byte6对应ASCII码";
CM_ SG_ 2499997256 D2P_Cfg3_HW_Ver_Byte7_08 "DCDC硬件版本号Byte7对应ASCII码";
CM_ SG_ 2499997257 D2P_Cfg3_HW_Ver_Byte0_09 "DCDC硬件版本号最低字节Byte0对应ASCII码";
CM_ SG_ 2499997257 D2P_Cfg3_HW_Ver_Byte1_09 "DCDC硬件版本号Byte1对应ASCII码";
CM_ SG_ 2499997257 D2P_Cfg3_HW_Ver_Byte2_09 "DCDC硬件版本号Byte2对应ASCII码";
CM_ SG_ 2499997257 D2P_Cfg3_HW_Ver_Byte3_09 "DCDC硬件版本号Byte3对应ASCII码";
CM_ SG_ 2499997257 D2P_Cfg3_HW_Ver_Byte4_09 "DCDC硬件版本号Byte4对应ASCII码";
CM_ SG_ 2499997257 D2P_Cfg3_HW_Ver_Byte5_09 "DCDC硬件版本号Byte5对应ASCII码";
CM_ SG_ 2499997257 D2P_Cfg3_HW_Ver_Byte6_09 "DCDC硬件版本号Byte6对应ASCII码";
CM_ SG_ 2499997257 D2P_Cfg3_HW_Ver_Byte7_09 "DCDC硬件版本号Byte7对应ASCII码";
VERSION ""

NS_ :

BS_:

BU_: MBMU PC SBMU IMM ETH DCDC LEMS

BO_ 2500128381 D2P_Cfg5__61: 8 DCDC
 SG_ D2P_Cfg5_Barcode0_61 : 0|8@1+ (1,0) [0|255] ""  PC
 SG_ D2P_Cfg5_Barcode1_61 : 8|8@1+ (1,0) [0|255] ""  PC
 SG_ D2P_Cfg5_Barcode2_61 : 16|8@1+ (1,0) [0|255] ""  PC
 SG_ D2P_Cfg5_Barcode3_61 : 24|8@1+ (1,0) [0|255] ""  PC
 SG_ D2P_Cfg5_Barcode4_61 : 32|8@1+ (1,0) [0|255] ""  PC
 SG_ D2P_Cfg5_Barcode5_61 : 40|8@1+ (1,0) [0|255] ""  PC
 SG_ D2P_Cfg5_Barcode6_61 : 48|8@1+ (1,0) [0|255] ""  PC
 SG_ D2P_Cfg5_Barcode7_61 : 56|8@1+ (1,0) [0|255] ""  PC

BO_ 2500128382 D2P_Cfg5__62: 8 DCDC
 SG_ D2P_Cfg5_Barcode0_62 : 0|8@1+ (1,0) [0|255] ""  PC
 SG_ D2P_Cfg5_Barcode1_62 : 8|8@1+ (1,0) [0|255] ""  PC
 SG_ D2P_Cfg5_Barcode2_62 : 16|8@1+ (1,0) [0|255] ""  PC
 SG_ D2P_Cfg5_Barcode3_62 : 24|8@1+ (1,0) [0|255] ""  PC
 SG_ D2P_Cfg5_Barcode4_62 : 32|8@1+ (1,0) [0|255] ""  PC
 SG_ D2P_Cfg5_Barcode5_62 : 40|8@1+ (1,0) [0|255] ""  PC
 SG_ D2P_Cfg5_Barcode6_62 : 48|8@1+ (1,0) [0|255] ""  PC
 SG_ D2P_Cfg5_Barcode7_62 : 56|8@1+ (1,0) [0|255] ""  PC

BO_ 2500128383 D2P_Cfg5__63: 8 DCDC
 SG_ D2P_Cfg5_Barcode0_63 : 0|8@1+ (1,0) [0|255] ""  PC
 SG_ D2P_Cfg5_Barcode1_63 : 8|8@1+ (1,0) [0|255] ""  PC
 SG_ D2P_Cfg5_Barcode2_63 : 16|8@1+ (1,0) [0|255] ""  PC
 SG_ D2P_Cfg5_Barcode3_63 : 24|8@1+ (1,0) [0|255] ""  PC
 SG_ D2P_Cfg5_Barcode4_63 : 32|8@1+ (1,0) [0|255] ""  PC
 SG_ D2P_Cfg5_Barcode5_63 : 40|8@1+ (1,0) [0|255] ""  PC
 SG_ D2P_Cfg5_Barcode6_63 : 48|8@1+ (1,0) [0|255] ""  PC
 SG_ D2P_Cfg5_Barcode7_63 : 56|8@1+ (1,0) [0|255] ""  PC

BO_ 2500193857 D2P_WriteOK__01: 8 DCDC
 SG_ D2P_WriteOK_Byte0_01 : 0|8@1+ (1,0) [0|255] ""  PC
 SG_ D2P_WriteOK_Byte1_01 : 8|8@1+ (1,0) [0|255] ""  PC
 SG_ D2P_WriteOK_Byte2_01 : 16|8@1+ (1,0) [0|255] ""  PC
 SG_ D2P_WriteOK_Byte3_01 : 24|8@1+ (1,0) [0|255] ""  PC
 SG_ D2P_WriteOK_Byte4_01 : 32|8@1+ (1,0) [0|255] ""  PC
 SG_ D2P_WriteOK_Byte5_01 : 40|8@1+ (1,0) [0|255] ""  PC
 SG_ D2P_WriteOK_Byte6_01 : 48|8@1+ (1,0) [0|255] ""  PC
 SG_ D2P_WriteOK_Byte7_01 : 56|8@1+ (1,0) [0|255] ""  PC

BO_ 2500193858 D2P_WriteOK__02: 8 DCDC
 SG_ D2P_WriteOK_Byte0_02 : 0|8@1+ (1,0) [0|255] ""  PC
 SG_ D2P_WriteOK_Byte1_02 : 8|8@1+ (1,0) [0|255] ""  PC
 SG_ D2P_WriteOK_Byte2_02 : 16|8@1+ (1,0) [0|255] ""  PC
 SG_ D2P_WriteOK_Byte3_02 : 24|8@1+ (1,0) [0|255] ""  PC
 SG_ D2P_WriteOK_Byte4_02 : 32|8@1+ (1,0) [0|255] ""  PC
 SG_ D2P_WriteOK_Byte5_02 : 40|8@1+ (1,0) [0|255] ""  PC
 SG_ D2P_WriteOK_Byte6_02 : 48|8@1+ (1,0) [0|255] ""  PC
 SG_ D2P_WriteOK_Byte7_02 : 56|8@1+ (1,0) [0|255] ""  PC

BO_ 2500193859 D2P_WriteOK__03: 8 DCDC
 SG_ D2P_WriteOK_Byte0_03 : 0|8@1+ (1,0) [0|255] ""  PC
 SG_ D2P_WriteOK_Byte1_03 : 8|8@1+ (1,0) [0|255] ""  PC
 SG_ D2P_WriteOK_Byte2_03 : 16|8@1+ (1,0) [0|255] ""  PC
 SG_ D2P_WriteOK_Byte3_03 : 24|8@1+ (1,0) [0|255] ""  PC
 SG_ D2P_WriteOK_Byte4_03 : 32|8@1+ (1,0) [0|255] ""  PC
 SG_ D2P_WriteOK_Byte5_03 : 40|8@1+ (1,0) [0|255] ""  PC
 SG_ D2P_WriteOK_Byte6_03 : 48|8@1+ (1,0) [0|255] ""  PC
 SG_ D2P_WriteOK_Byte7_03 : 56|8@1+ (1,0) [0|255] ""  PC

BO_ 2500193860 D2P_WriteOK__04: 8 DCDC
 SG_ D2P_WriteOK_Byte0_04 : 0|8@1+ (1,0) [0|255] ""  PC
 SG_ D2P_WriteOK_Byte1_04 : 8|8@1+ (1,0) [0|255] ""  PC
 SG_ D2P_WriteOK_Byte2_04 : 16|8@1+ (1,0) [0|255] ""  PC
 SG_ D2P_WriteOK_Byte3_04 : 24|8@1+ (1,0) [0|255] ""  PC
 SG_ D2P_WriteOK_Byte4_04 : 32|8@1+ (1,0) [0|255] ""  PC
 SG_ D2P_WriteOK_Byte5_04 : 40|8@1+ (1,0) [0|255] ""  PC
 SG_ D2P_WriteOK_Byte6_04 : 48|8@1+ (1,0) [0|255] ""  PC
 SG_ D2P_WriteOK_Byte7_04 : 56|8@1+ (1,0) [0|255] ""  PC

BO_ 2500193861 D2P_WriteOK__05: 8 DCDC
 SG_ D2P_WriteOK_Byte0_05 : 0|8@1+ (1,0) [0|255] ""  PC
 SG_ D2P_WriteOK_Byte1_05 : 8|8@1+ (1,0) [0|255] ""  PC
 SG_ D2P_WriteOK_Byte2_05 : 16|8@1+ (1,0) [0|255] ""  PC
 SG_ D2P_WriteOK_Byte3_05 : 24|8@1+ (1,0) [0|255] ""  PC
 SG_ D2P_WriteOK_Byte4_05 : 32|8@1+ (1,0) [0|255] ""  PC
 SG_ D2P_WriteOK_Byte5_05 : 40|8@1+ (1,0) [0|255] ""  PC
 SG_ D2P_WriteOK_Byte6_05 : 48|8@1+ (1,0) [0|255] ""  PC
 SG_ D2P_WriteOK_Byte7_05 : 56|8@1+ (1,0) [0|255] ""  PC

BO_ 2500193862 D2P_WriteOK__06: 8 DCDC
 SG_ D2P_WriteOK_Byte0_06 : 0|8@1+ (1,0) [0|255] ""  PC
 SG_ D2P_WriteOK_Byte1_06 : 8|8@1+ (1,0) [0|255] ""  PC
 SG_ D2P_WriteOK_Byte2_06 : 16|8@1+ (1,0) [0|255] ""  PC
 SG_ D2P_WriteOK_Byte3_06 : 24|8@1+ (1,0) [0|255] ""  PC
 SG_ D2P_WriteOK_Byte4_06 : 32|8@1+ (1,0) [0|255] ""  PC
 SG_ D2P_WriteOK_Byte5_06 : 40|8@1+ (1,0) [0|255] ""  PC
 SG_ D2P_WriteOK_Byte6_06 : 48|8@1+ (1,0) [0|255] ""  PC
 SG_ D2P_WriteOK_Byte7_06 : 56|8@1+ (1,0) [0|255] ""  PC

BO_ 2500193863 D2P_WriteOK__07: 8 DCDC
 SG_ D2P_WriteOK_Byte0_07 : 0|8@1+ (1,0) [0|255] ""  PC
 SG_ D2P_WriteOK_Byte1_07 : 8|8@1+ (1,0) [0|255] ""  PC
 SG_ D2P_WriteOK_Byte2_07 : 16|8@1+ (1,0) [0|255] ""  PC
 SG_ D2P_WriteOK_Byte3_07 : 24|8@1+ (1,0) [0|255] ""  PC
 SG_ D2P_WriteOK_Byte4_07 : 32|8@1+ (1,0) [0|255] ""  PC
 SG_ D2P_WriteOK_Byte5_07 : 40|8@1+ (1,0) [0|255] ""  PC
 SG_ D2P_WriteOK_Byte6_07 : 48|8@1+ (1,0) [0|255] ""  PC
 SG_ D2P_WriteOK_Byte7_07 : 56|8@1+ (1,0) [0|255] ""  PC

BO_ 2500193864 D2P_WriteOK__08: 8 DCDC
 SG_ D2P_WriteOK_Byte0_08 : 0|8@1+ (1,0) [0|255] ""  PC
 SG_ D2P_WriteOK_Byte1_08 : 8|8@1+ (1,0) [0|255] ""  PC
 SG_ D2P_WriteOK_Byte2_08 : 16|8@1+ (1,0) [0|255] ""  PC
 SG_ D2P_WriteOK_Byte3_08 : 24|8@1+ (1,0) [0|255] ""  PC
 SG_ D2P_WriteOK_Byte4_08 : 32|8@1+ (1,0) [0|255] ""  PC
 SG_ D2P_WriteOK_Byte5_08 : 40|8@1+ (1,0) [0|255] ""  PC
 SG_ D2P_WriteOK_Byte6_08 : 48|8@1+ (1,0) [0|255] ""  PC
 SG_ D2P_WriteOK_Byte7_08 : 56|8@1+ (1,0) [0|255] ""  PC

BO_ 2500193865 D2P_WriteOK__09: 8 DCDC
 SG_ D2P_WriteOK_Byte0_09 : 0|8@1+ (1,0) [0|255] ""  PC
 SG_ D2P_WriteOK_Byte1_09 : 8|8@1+ (1,0) [0|255] ""  PC
 SG_ D2P_WriteOK_Byte2_09 : 16|8@1+ (1,0) [0|255] ""  PC
 SG_ D2P_WriteOK_Byte3_09 : 24|8@1+ (1,0) [0|255] ""  PC
 SG_ D2P_WriteOK_Byte4_09 : 32|8@1+ (1,0) [0|255] ""  PC
 SG_ D2P_WriteOK_Byte5_09 : 40|8@1+ (1,0) [0|255] ""  PC
 SG_ D2P_WriteOK_Byte6_09 : 48|8@1+ (1,0) [0|255] ""  PC
 SG_ D2P_WriteOK_Byte7_09 : 56|8@1+ (1,0) [0|255] ""  PC

BO_ 2500193866 D2P_WriteOK__10: 8 DCDC
 SG_ D2P_WriteOK_Byte0_10 : 0|8@1+ (1,0) [0|255] ""  PC
 SG_ D2P_WriteOK_Byte1_10 : 8|8@1+ (1,0) [0|255] ""  PC
 SG_ D2P_WriteOK_Byte2_10 : 16|8@1+ (1,0) [0|255] ""  PC
 SG_ D2P_WriteOK_Byte3_10 : 24|8@1+ (1,0) [0|255] ""  PC
 SG_ D2P_WriteOK_Byte4_10 : 32|8@1+ (1,0) [0|255] ""  PC
 SG_ D2P_WriteOK_Byte5_10 : 40|8@1+ (1,0) [0|255] ""  PC
 SG_ D2P_WriteOK_Byte6_10 : 48|8@1+ (1,0) [0|255] ""  PC
 SG_ D2P_WriteOK_Byte7_10 : 56|8@1+ (1,0) [0|255] ""  PC

BO_ 2500193867 D2P_WriteOK__11: 8 DCDC
 SG_ D2P_WriteOK_Byte0_11 : 0|8@1+ (1,0) [0|255] ""  PC
 SG_ D2P_WriteOK_Byte1_11 : 8|8@1+ (1,0) [0|255] ""  PC
 SG_ D2P_WriteOK_Byte2_11 : 16|8@1+ (1,0) [0|255] ""  PC
 SG_ D2P_WriteOK_Byte3_11 : 24|8@1+ (1,0) [0|255] ""  PC
 SG_ D2P_WriteOK_Byte4_11 : 32|8@1+ (1,0) [0|255] ""  PC
 SG_ D2P_WriteOK_Byte5_11 : 40|8@1+ (1,0) [0|255] ""  PC
 SG_ D2P_WriteOK_Byte6_11 : 48|8@1+ (1,0) [0|255] ""  PC
 SG_ D2P_WriteOK_Byte7_11 : 56|8@1+ (1,0) [0|255] ""  PC

BO_ 2500193868 D2P_WriteOK__12: 8 DCDC
 SG_ D2P_WriteOK_Byte0_12 : 0|8@1+ (1,0) [0|255] ""  PC
 SG_ D2P_WriteOK_Byte1_12 : 8|8@1+ (1,0) [0|255] ""  PC
 SG_ D2P_WriteOK_Byte2_12 : 16|8@1+ (1,0) [0|255] ""  PC
 SG_ D2P_WriteOK_Byte3_12 : 24|8@1+ (1,0) [0|255] ""  PC
 SG_ D2P_WriteOK_Byte4_12 : 32|8@1+ (1,0) [0|255] ""  PC
 SG_ D2P_WriteOK_Byte5_12 : 40|8@1+ (1,0) [0|255] ""  PC
 SG_ D2P_WriteOK_Byte6_12 : 48|8@1+ (1,0) [0|255] ""  PC
 SG_ D2P_WriteOK_Byte7_12 : 56|8@1+ (1,0) [0|255] ""  PC

BO_ 2500193869 D2P_WriteOK__13: 8 DCDC
 SG_ D2P_WriteOK_Byte0_13 : 0|8@1+ (1,0) [0|255] ""  PC
 SG_ D2P_WriteOK_Byte1_13 : 8|8@1+ (1,0) [0|255] ""  PC
 SG_ D2P_WriteOK_Byte2_13 : 16|8@1+ (1,0) [0|255] ""  PC
 SG_ D2P_WriteOK_Byte3_13 : 24|8@1+ (1,0) [0|255] ""  PC
 SG_ D2P_WriteOK_Byte4_13 : 32|8@1+ (1,0) [0|255] ""  PC
 SG_ D2P_WriteOK_Byte5_13 : 40|8@1+ (1,0) [0|255] ""  PC
 SG_ D2P_WriteOK_Byte6_13 : 48|8@1+ (1,0) [0|255] ""  PC
 SG_ D2P_WriteOK_Byte7_13 : 56|8@1+ (1,0) [0|255] ""  PC

BO_ 2500193870 D2P_WriteOK__14: 8 DCDC
 SG_ D2P_WriteOK_Byte0_14 : 0|8@1+ (1,0) [0|255] ""  PC
 SG_ D2P_WriteOK_Byte1_14 : 8|8@1+ (1,0) [0|255] ""  PC
 SG_ D2P_WriteOK_Byte2_14 : 16|8@1+ (1,0) [0|255] ""  PC
 SG_ D2P_WriteOK_Byte3_14 : 24|8@1+ (1,0) [0|255] ""  PC
 SG_ D2P_WriteOK_Byte4_14 : 32|8@1+ (1,0) [0|255] ""  PC
 SG_ D2P_WriteOK_Byte5_14 : 40|8@1+ (1,0) [0|255] ""  PC
 SG_ D2P_WriteOK_Byte6_14 : 48|8@1+ (1,0) [0|255] ""  PC
 SG_ D2P_WriteOK_Byte7_14 : 56|8@1+ (1,0) [0|255] ""  PC

BO_ 2500193871 D2P_WriteOK__15: 8 DCDC
 SG_ D2P_WriteOK_Byte0_15 : 0|8@1+ (1,0) [0|255] ""  PC
 SG_ D2P_WriteOK_Byte1_15 : 8|8@1+ (1,0) [0|255] ""  PC
 SG_ D2P_WriteOK_Byte2_15 : 16|8@1+ (1,0) [0|255] ""  PC
 SG_ D2P_WriteOK_Byte3_15 : 24|8@1+ (1,0) [0|255] ""  PC
 SG_ D2P_WriteOK_Byte4_15 : 32|8@1+ (1,0) [0|255] ""  PC
 SG_ D2P_WriteOK_Byte5_15 : 40|8@1+ (1,0) [0|255] ""  PC
 SG_ D2P_WriteOK_Byte6_15 : 48|8@1+ (1,0) [0|255] ""  PC
 SG_ D2P_WriteOK_Byte7_15 : 56|8@1+ (1,0) [0|255] ""  PC

BO_ 2500193872 D2P_WriteOK__16: 8 DCDC
 SG_ D2P_WriteOK_Byte0_16 : 0|8@1+ (1,0) [0|255] ""  PC
 SG_ D2P_WriteOK_Byte1_16 : 8|8@1+ (1,0) [0|255] ""  PC
 SG_ D2P_WriteOK_Byte2_16 : 16|8@1+ (1,0) [0|255] ""  PC
 SG_ D2P_WriteOK_Byte3_16 : 24|8@1+ (1,0) [0|255] ""  PC
 SG_ D2P_WriteOK_Byte4_16 : 32|8@1+ (1,0) [0|255] ""  PC
 SG_ D2P_WriteOK_Byte5_16 : 40|8@1+ (1,0) [0|255] ""  PC
 SG_ D2P_WriteOK_Byte6_16 : 48|8@1+ (1,0) [0|255] ""  PC
 SG_ D2P_WriteOK_Byte7_16 : 56|8@1+ (1,0) [0|255] ""  PC

BO_ 2500193873 D2P_WriteOK__17: 8 DCDC
 SG_ D2P_WriteOK_Byte0_17 : 0|8@1+ (1,0) [0|255] ""  PC
 SG_ D2P_WriteOK_Byte1_17 : 8|8@1+ (1,0) [0|255] ""  PC
 SG_ D2P_WriteOK_Byte2_17 : 16|8@1+ (1,0) [0|255] ""  PC
 SG_ D2P_WriteOK_Byte3_17 : 24|8@1+ (1,0) [0|255] ""  PC
 SG_ D2P_WriteOK_Byte4_17 : 32|8@1+ (1,0) [0|255] ""  PC
 SG_ D2P_WriteOK_Byte5_17 : 40|8@1+ (1,0) [0|255] ""  PC
 SG_ D2P_WriteOK_Byte6_17 : 48|8@1+ (1,0) [0|255] ""  PC
 SG_ D2P_WriteOK_Byte7_17 : 56|8@1+ (1,0) [0|255] ""  PC

BO_ 2500193874 D2P_WriteOK__18: 8 DCDC
 SG_ D2P_WriteOK_Byte0_18 : 0|8@1+ (1,0) [0|255] ""  PC
 SG_ D2P_WriteOK_Byte1_18 : 8|8@1+ (1,0) [0|255] ""  PC
 SG_ D2P_WriteOK_Byte2_18 : 16|8@1+ (1,0) [0|255] ""  PC
 SG_ D2P_WriteOK_Byte3_18 : 24|8@1+ (1,0) [0|255] ""  PC
 SG_ D2P_WriteOK_Byte4_18 : 32|8@1+ (1,0) [0|255] ""  PC
 SG_ D2P_WriteOK_Byte5_18 : 40|8@1+ (1,0) [0|255] ""  PC
 SG_ D2P_WriteOK_Byte6_18 : 48|8@1+ (1,0) [0|255] ""  PC
 SG_ D2P_WriteOK_Byte7_18 : 56|8@1+ (1,0) [0|255] ""  PC

BO_ 2500193875 D2P_WriteOK__19: 8 DCDC
 SG_ D2P_WriteOK_Byte0_19 : 0|8@1+ (1,0) [0|255] ""  PC
 SG_ D2P_WriteOK_Byte1_19 : 8|8@1+ (1,0) [0|255] ""  PC
 SG_ D2P_WriteOK_Byte2_19 : 16|8@1+ (1,0) [0|255] ""  PC
 SG_ D2P_WriteOK_Byte3_19 : 24|8@1+ (1,0) [0|255] ""  PC
 SG_ D2P_WriteOK_Byte4_19 : 32|8@1+ (1,0) [0|255] ""  PC
 SG_ D2P_WriteOK_Byte5_19 : 40|8@1+ (1,0) [0|255] ""  PC
 SG_ D2P_WriteOK_Byte6_19 : 48|8@1+ (1,0) [0|255] ""  PC
 SG_ D2P_WriteOK_Byte7_19 : 56|8@1+ (1,0) [0|255] ""  PC

BO_ 2500193876 D2P_WriteOK__20: 8 DCDC
 SG_ D2P_WriteOK_Byte0_20 : 0|8@1+ (1,0) [0|255] ""  PC
 SG_ D2P_WriteOK_Byte1_20 : 8|8@1+ (1,0) [0|255] ""  PC
 SG_ D2P_WriteOK_Byte2_20 : 16|8@1+ (1,0) [0|255] ""  PC
 SG_ D2P_WriteOK_Byte3_20 : 24|8@1+ (1,0) [0|255] ""  PC
 SG_ D2P_WriteOK_Byte4_20 : 32|8@1+ (1,0) [0|255] ""  PC
 SG_ D2P_WriteOK_Byte5_20 : 40|8@1+ (1,0) [0|255] ""  PC
 SG_ D2P_WriteOK_Byte6_20 : 48|8@1+ (1,0) [0|255] ""  PC
 SG_ D2P_WriteOK_Byte7_20 : 56|8@1+ (1,0) [0|255] ""  PC

BO_ 2500193877 D2P_WriteOK__21: 8 DCDC
 SG_ D2P_WriteOK_Byte0_21 : 0|8@1+ (1,0) [0|255] ""  PC
 SG_ D2P_WriteOK_Byte1_21 : 8|8@1+ (1,0) [0|255] ""  PC
 SG_ D2P_WriteOK_Byte2_21 : 16|8@1+ (1,0) [0|255] ""  PC
 SG_ D2P_WriteOK_Byte3_21 : 24|8@1+ (1,0) [0|255] ""  PC
 SG_ D2P_WriteOK_Byte4_21 : 32|8@1+ (1,0) [0|255] ""  PC
 SG_ D2P_WriteOK_Byte5_21 : 40|8@1+ (1,0) [0|255] ""  PC
 SG_ D2P_WriteOK_Byte6_21 : 48|8@1+ (1,0) [0|255] ""  PC
 SG_ D2P_WriteOK_Byte7_21 : 56|8@1+ (1,0) [0|255] ""  PC

BO_ 2500193878 D2P_WriteOK__22: 8 DCDC
 SG_ D2P_WriteOK_Byte0_22 : 0|8@1+ (1,0) [0|255] ""  PC
 SG_ D2P_WriteOK_Byte1_22 : 8|8@1+ (1,0) [0|255] ""  PC
 SG_ D2P_WriteOK_Byte2_22 : 16|8@1+ (1,0) [0|255] ""  PC
 SG_ D2P_WriteOK_Byte3_22 : 24|8@1+ (1,0) [0|255] ""  PC
 SG_ D2P_WriteOK_Byte4_22 : 32|8@1+ (1,0) [0|255] ""  PC
 SG_ D2P_WriteOK_Byte5_22 : 40|8@1+ (1,0) [0|255] ""  PC
 SG_ D2P_WriteOK_Byte6_22 : 48|8@1+ (1,0) [0|255] ""  PC
 SG_ D2P_WriteOK_Byte7_22 : 56|8@1+ (1,0) [0|255] ""  PC

BO_ 2500193879 D2P_WriteOK__23: 8 DCDC
 SG_ D2P_WriteOK_Byte0_23 : 0|8@1+ (1,0) [0|255] ""  PC
 SG_ D2P_WriteOK_Byte1_23 : 8|8@1+ (1,0) [0|255] ""  PC
 SG_ D2P_WriteOK_Byte2_23 : 16|8@1+ (1,0) [0|255] ""  PC
 SG_ D2P_WriteOK_Byte3_23 : 24|8@1+ (1,0) [0|255] ""  PC
 SG_ D2P_WriteOK_Byte4_23 : 32|8@1+ (1,0) [0|255] ""  PC
 SG_ D2P_WriteOK_Byte5_23 : 40|8@1+ (1,0) [0|255] ""  PC
 SG_ D2P_WriteOK_Byte6_23 : 48|8@1+ (1,0) [0|255] ""  PC
 SG_ D2P_WriteOK_Byte7_23 : 56|8@1+ (1,0) [0|255] ""  PC

BO_ 2500193880 D2P_WriteOK__24: 8 DCDC
 SG_ D2P_WriteOK_Byte0_24 : 0|8@1+ (1,0) [0|255] ""  PC
 SG_ D2P_WriteOK_Byte1_24 : 8|8@1+ (1,0) [0|255] ""  PC
 SG_ D2P_WriteOK_Byte2_24 : 16|8@1+ (1,0) [0|255] ""  PC
 SG_ D2P_WriteOK_Byte3_24 : 24|8@1+ (1,0) [0|255] ""  PC
 SG_ D2P_WriteOK_Byte4_24 : 32|8@1+ (1,0) [0|255] ""  PC
 SG_ D2P_WriteOK_Byte5_24 : 40|8@1+ (1,0) [0|255] ""  PC
 SG_ D2P_WriteOK_Byte6_24 : 48|8@1+ (1,0) [0|255] ""  PC
 SG_ D2P_WriteOK_Byte7_24 : 56|8@1+ (1,0) [0|255] ""  PC

BO_ 2500193881 D2P_WriteOK__25: 8 DCDC
 SG_ D2P_WriteOK_Byte0_25 : 0|8@1+ (1,0) [0|255] ""  PC
 SG_ D2P_WriteOK_Byte1_25 : 8|8@1+ (1,0) [0|255] ""  PC
 SG_ D2P_WriteOK_Byte2_25 : 16|8@1+ (1,0) [0|255] ""  PC
 SG_ D2P_WriteOK_Byte3_25 : 24|8@1+ (1,0) [0|255] ""  PC
 SG_ D2P_WriteOK_Byte4_25 : 32|8@1+ (1,0) [0|255] ""  PC
 SG_ D2P_WriteOK_Byte5_25 : 40|8@1+ (1,0) [0|255] ""  PC
 SG_ D2P_WriteOK_Byte6_25 : 48|8@1+ (1,0) [0|255] ""  PC
 SG_ D2P_WriteOK_Byte7_25 : 56|8@1+ (1,0) [0|255] ""  PC

BO_ 2500193882 D2P_WriteOK__26: 8 DCDC
 SG_ D2P_WriteOK_Byte0_26 : 0|8@1+ (1,0) [0|255] ""  PC
 SG_ D2P_WriteOK_Byte1_26 : 8|8@1+ (1,0) [0|255] ""  PC
 SG_ D2P_WriteOK_Byte2_26 : 16|8@1+ (1,0) [0|255] ""  PC
 SG_ D2P_WriteOK_Byte3_26 : 24|8@1+ (1,0) [0|255] ""  PC
 SG_ D2P_WriteOK_Byte4_26 : 32|8@1+ (1,0) [0|255] ""  PC
 SG_ D2P_WriteOK_Byte5_26 : 40|8@1+ (1,0) [0|255] ""  PC
 SG_ D2P_WriteOK_Byte6_26 : 48|8@1+ (1,0) [0|255] ""  PC
 SG_ D2P_WriteOK_Byte7_26 : 56|8@1+ (1,0) [0|255] ""  PC

BO_ 2500193883 D2P_WriteOK__27: 8 DCDC
 SG_ D2P_WriteOK_Byte0_27 : 0|8@1+ (1,0) [0|255] ""  PC
 SG_ D2P_WriteOK_Byte1_27 : 8|8@1+ (1,0) [0|255] ""  PC
 SG_ D2P_WriteOK_Byte2_27 : 16|8@1+ (1,0) [0|255] ""  PC
 SG_ D2P_WriteOK_Byte3_27 : 24|8@1+ (1,0) [0|255] ""  PC
 SG_ D2P_WriteOK_Byte4_27 : 32|8@1+ (1,0) [0|255] ""  PC
 SG_ D2P_WriteOK_Byte5_27 : 40|8@1+ (1,0) [0|255] ""  PC
 SG_ D2P_WriteOK_Byte6_27 : 48|8@1+ (1,0) [0|255] ""  PC
 SG_ D2P_WriteOK_Byte7_27 : 56|8@1+ (1,0) [0|255] ""  PC

BO_ 2500193884 D2P_WriteOK__28: 8 DCDC
 SG_ D2P_WriteOK_Byte0_28 : 0|8@1+ (1,0) [0|255] ""  PC
 SG_ D2P_WriteOK_Byte1_28 : 8|8@1+ (1,0) [0|255] ""  PC
 SG_ D2P_WriteOK_Byte2_28 : 16|8@1+ (1,0) [0|255] ""  PC
 SG_ D2P_WriteOK_Byte3_28 : 24|8@1+ (1,0) [0|255] ""  PC
 SG_ D2P_WriteOK_Byte4_28 : 32|8@1+ (1,0) [0|255] ""  PC
 SG_ D2P_WriteOK_Byte5_28 : 40|8@1+ (1,0) [0|255] ""  PC
 SG_ D2P_WriteOK_Byte6_28 : 48|8@1+ (1,0) [0|255] ""  PC
 SG_ D2P_WriteOK_Byte7_28 : 56|8@1+ (1,0) [0|255] ""  PC

BO_ 2500193885 D2P_WriteOK__29: 8 DCDC
 SG_ D2P_WriteOK_Byte0_29 : 0|8@1+ (1,0) [0|255] ""  PC
 SG_ D2P_WriteOK_Byte1_29 : 8|8@1+ (1,0) [0|255] ""  PC
 SG_ D2P_WriteOK_Byte2_29 : 16|8@1+ (1,0) [0|255] ""  PC
 SG_ D2P_WriteOK_Byte3_29 : 24|8@1+ (1,0) [0|255] ""  PC
 SG_ D2P_WriteOK_Byte4_29 : 32|8@1+ (1,0) [0|255] ""  PC
 SG_ D2P_WriteOK_Byte5_29 : 40|8@1+ (1,0) [0|255] ""  PC
 SG_ D2P_WriteOK_Byte6_29 : 48|8@1+ (1,0) [0|255] ""  PC
 SG_ D2P_WriteOK_Byte7_29 : 56|8@1+ (1,0) [0|255] ""  PC

BO_ 2500193886 D2P_WriteOK__30: 8 DCDC
 SG_ D2P_WriteOK_Byte0_30 : 0|8@1+ (1,0) [0|255] ""  PC
 SG_ D2P_WriteOK_Byte1_30 : 8|8@1+ (1,0) [0|255] ""  PC
 SG_ D2P_WriteOK_Byte2_30 : 16|8@1+ (1,0) [0|255] ""  PC
 SG_ D2P_WriteOK_Byte3_30 : 24|8@1+ (1,0) [0|255] ""  PC
 SG_ D2P_WriteOK_Byte4_30 : 32|8@1+ (1,0) [0|255] ""  PC
 SG_ D2P_WriteOK_Byte5_30 : 40|8@1+ (1,0) [0|255] ""  PC
 SG_ D2P_WriteOK_Byte6_30 : 48|8@1+ (1,0) [0|255] ""  PC
 SG_ D2P_WriteOK_Byte7_30 : 56|8@1+ (1,0) [0|255] ""  PC

BO_ 2500193887 D2P_WriteOK__31: 8 DCDC
 SG_ D2P_WriteOK_Byte0_31 : 0|8@1+ (1,0) [0|255] ""  PC
 SG_ D2P_WriteOK_Byte1_31 : 8|8@1+ (1,0) [0|255] ""  PC
 SG_ D2P_WriteOK_Byte2_31 : 16|8@1+ (1,0) [0|255] ""  PC
 SG_ D2P_WriteOK_Byte3_31 : 24|8@1+ (1,0) [0|255] ""  PC
 SG_ D2P_WriteOK_Byte4_31 : 32|8@1+ (1,0) [0|255] ""  PC
 SG_ D2P_WriteOK_Byte5_31 : 40|8@1+ (1,0) [0|255] ""  PC
 SG_ D2P_WriteOK_Byte6_31 : 48|8@1+ (1,0) [0|255] ""  PC
 SG_ D2P_WriteOK_Byte7_31 : 56|8@1+ (1,0) [0|255] ""  PC

BO_ 2500193888 D2P_WriteOK__32: 8 DCDC
 SG_ D2P_WriteOK_Byte0_32 : 0|8@1+ (1,0) [0|255] ""  PC
 SG_ D2P_WriteOK_Byte1_32 : 8|8@1+ (1,0) [0|255] ""  PC
 SG_ D2P_WriteOK_Byte2_32 : 16|8@1+ (1,0) [0|255] ""  PC
 SG_ D2P_WriteOK_Byte3_32 : 24|8@1+ (1,0) [0|255] ""  PC
 SG_ D2P_WriteOK_Byte4_32 : 32|8@1+ (1,0) [0|255] ""  PC
 SG_ D2P_WriteOK_Byte5_32 : 40|8@1+ (1,0) [0|255] ""  PC
 SG_ D2P_WriteOK_Byte6_32 : 48|8@1+ (1,0) [0|255] ""  PC
 SG_ D2P_WriteOK_Byte7_32 : 56|8@1+ (1,0) [0|255] ""  PC

BO_ 2500193889 D2P_WriteOK__33: 8 DCDC
 SG_ D2P_WriteOK_Byte0_33 : 0|8@1+ (1,0) [0|255] ""  PC
 SG_ D2P_WriteOK_Byte1_33 : 8|8@1+ (1,0) [0|255] ""  PC
 SG_ D2P_WriteOK_Byte2_33 : 16|8@1+ (1,0) [0|255] ""  PC
 SG_ D2P_WriteOK_Byte3_33 : 24|8@1+ (1,0) [0|255] ""  PC
 SG_ D2P_WriteOK_Byte4_33 : 32|8@1+ (1,0) [0|255] ""  PC
 SG_ D2P_WriteOK_Byte5_33 : 40|8@1+ (1,0) [0|255] ""  PC
 SG_ D2P_WriteOK_Byte6_33 : 48|8@1+ (1,0) [0|255] ""  PC
 SG_ D2P_WriteOK_Byte7_33 : 56|8@1+ (1,0) [0|255] ""  PC

BO_ 2500193890 D2P_WriteOK__34: 8 DCDC
 SG_ D2P_WriteOK_Byte0_34 : 0|8@1+ (1,0) [0|255] ""  PC
 SG_ D2P_WriteOK_Byte1_34 : 8|8@1+ (1,0) [0|255] ""  PC
 SG_ D2P_WriteOK_Byte2_34 : 16|8@1+ (1,0) [0|255] ""  PC
 SG_ D2P_WriteOK_Byte3_34 : 24|8@1+ (1,0) [0|255] ""  PC
 SG_ D2P_WriteOK_Byte4_34 : 32|8@1+ (1,0) [0|255] ""  PC
 SG_ D2P_WriteOK_Byte5_34 : 40|8@1+ (1,0) [0|255] ""  PC
 SG_ D2P_WriteOK_Byte6_34 : 48|8@1+ (1,0) [0|255] ""  PC
 SG_ D2P_WriteOK_Byte7_34 : 56|8@1+ (1,0) [0|255] ""  PC

BO_ 2500193891 D2P_WriteOK__35: 8 DCDC
 SG_ D2P_WriteOK_Byte0_35 : 0|8@1+ (1,0) [0|255] ""  PC
 SG_ D2P_WriteOK_Byte1_35 : 8|8@1+ (1,0) [0|255] ""  PC
 SG_ D2P_WriteOK_Byte2_35 : 16|8@1+ (1,0) [0|255] ""  PC
 SG_ D2P_WriteOK_Byte3_35 : 24|8@1+ (1,0) [0|255] ""  PC
 SG_ D2P_WriteOK_Byte4_35 : 32|8@1+ (1,0) [0|255] ""  PC
 SG_ D2P_WriteOK_Byte5_35 : 40|8@1+ (1,0) [0|255] ""  PC
 SG_ D2P_WriteOK_Byte6_35 : 48|8@1+ (1,0) [0|255] ""  PC
 SG_ D2P_WriteOK_Byte7_35 : 56|8@1+ (1,0) [0|255] ""  PC

BO_ 2500193892 D2P_WriteOK__36: 8 DCDC
 SG_ D2P_WriteOK_Byte0_36 : 0|8@1+ (1,0) [0|255] ""  PC
 SG_ D2P_WriteOK_Byte1_36 : 8|8@1+ (1,0) [0|255] ""  PC
 SG_ D2P_WriteOK_Byte2_36 : 16|8@1+ (1,0) [0|255] ""  PC
 SG_ D2P_WriteOK_Byte3_36 : 24|8@1+ (1,0) [0|255] ""  PC
 SG_ D2P_WriteOK_Byte4_36 : 32|8@1+ (1,0) [0|255] ""  PC
 SG_ D2P_WriteOK_Byte5_36 : 40|8@1+ (1,0) [0|255] ""  PC
 SG_ D2P_WriteOK_Byte6_36 : 48|8@1+ (1,0) [0|255] ""  PC
 SG_ D2P_WriteOK_Byte7_36 : 56|8@1+ (1,0) [0|255] ""  PC

BO_ 2500193893 D2P_WriteOK__37: 8 DCDC
 SG_ D2P_WriteOK_Byte0_37 : 0|8@1+ (1,0) [0|255] ""  PC
 SG_ D2P_WriteOK_Byte1_37 : 8|8@1+ (1,0) [0|255] ""  PC
 SG_ D2P_WriteOK_Byte2_37 : 16|8@1+ (1,0) [0|255] ""  PC
 SG_ D2P_WriteOK_Byte3_37 : 24|8@1+ (1,0) [0|255] ""  PC
 SG_ D2P_WriteOK_Byte4_37 : 32|8@1+ (1,0) [0|255] ""  PC
 SG_ D2P_WriteOK_Byte5_37 : 40|8@1+ (1,0) [0|255] ""  PC
 SG_ D2P_WriteOK_Byte6_37 : 48|8@1+ (1,0) [0|255] ""  PC
 SG_ D2P_WriteOK_Byte7_37 : 56|8@1+ (1,0) [0|255] ""  PC

BO_ 2500193894 D2P_WriteOK__38: 8 DCDC
 SG_ D2P_WriteOK_Byte0_38 : 0|8@1+ (1,0) [0|255] ""  PC
 SG_ D2P_WriteOK_Byte1_38 : 8|8@1+ (1,0) [0|255] ""  PC
 SG_ D2P_WriteOK_Byte2_38 : 16|8@1+ (1,0) [0|255] ""  PC
 SG_ D2P_WriteOK_Byte3_38 : 24|8@1+ (1,0) [0|255] ""  PC
 SG_ D2P_WriteOK_Byte4_38 : 32|8@1+ (1,0) [0|255] ""  PC
 SG_ D2P_WriteOK_Byte5_38 : 40|8@1+ (1,0) [0|255] ""  PC
 SG_ D2P_WriteOK_Byte6_38 : 48|8@1+ (1,0) [0|255] ""  PC
 SG_ D2P_WriteOK_Byte7_38 : 56|8@1+ (1,0) [0|255] ""  PC

BO_ 2500193895 D2P_WriteOK__39: 8 DCDC
 SG_ D2P_WriteOK_Byte0_39 : 0|8@1+ (1,0) [0|255] ""  PC
 SG_ D2P_WriteOK_Byte1_39 : 8|8@1+ (1,0) [0|255] ""  PC
 SG_ D2P_WriteOK_Byte2_39 : 16|8@1+ (1,0) [0|255] ""  PC
 SG_ D2P_WriteOK_Byte3_39 : 24|8@1+ (1,0) [0|255] ""  PC
 SG_ D2P_WriteOK_Byte4_39 : 32|8@1+ (1,0) [0|255] ""  PC
 SG_ D2P_WriteOK_Byte5_39 : 40|8@1+ (1,0) [0|255] ""  PC
 SG_ D2P_WriteOK_Byte6_39 : 48|8@1+ (1,0) [0|255] ""  PC
 SG_ D2P_WriteOK_Byte7_39 : 56|8@1+ (1,0) [0|255] ""  PC

BO_ 2500193896 D2P_WriteOK__40: 8 DCDC
 SG_ D2P_WriteOK_Byte0_40 : 0|8@1+ (1,0) [0|255] ""  PC
 SG_ D2P_WriteOK_Byte1_40 : 8|8@1+ (1,0) [0|255] ""  PC
 SG_ D2P_WriteOK_Byte2_40 : 16|8@1+ (1,0) [0|255] ""  PC
 SG_ D2P_WriteOK_Byte3_40 : 24|8@1+ (1,0) [0|255] ""  PC
 SG_ D2P_WriteOK_Byte4_40 : 32|8@1+ (1,0) [0|255] ""  PC
 SG_ D2P_WriteOK_Byte5_40 : 40|8@1+ (1,0) [0|255] ""  PC
 SG_ D2P_WriteOK_Byte6_40 : 48|8@1+ (1,0) [0|255] ""  PC
 SG_ D2P_WriteOK_Byte7_40 : 56|8@1+ (1,0) [0|255] ""  PC

BO_ 2500193897 D2P_WriteOK__41: 8 DCDC
 SG_ D2P_WriteOK_Byte0_41 : 0|8@1+ (1,0) [0|255] ""  PC
 SG_ D2P_WriteOK_Byte1_41 : 8|8@1+ (1,0) [0|255] ""  PC
 SG_ D2P_WriteOK_Byte2_41 : 16|8@1+ (1,0) [0|255] ""  PC
 SG_ D2P_WriteOK_Byte3_41 : 24|8@1+ (1,0) [0|255] ""  PC
 SG_ D2P_WriteOK_Byte4_41 : 32|8@1+ (1,0) [0|255] ""  PC
 SG_ D2P_WriteOK_Byte5_41 : 40|8@1+ (1,0) [0|255] ""  PC
 SG_ D2P_WriteOK_Byte6_41 : 48|8@1+ (1,0) [0|255] ""  PC
 SG_ D2P_WriteOK_Byte7_41 : 56|8@1+ (1,0) [0|255] ""  PC

BO_ 2500193898 D2P_WriteOK__42: 8 DCDC
 SG_ D2P_WriteOK_Byte0_42 : 0|8@1+ (1,0) [0|255] ""  PC
 SG_ D2P_WriteOK_Byte1_42 : 8|8@1+ (1,0) [0|255] ""  PC
 SG_ D2P_WriteOK_Byte2_42 : 16|8@1+ (1,0) [0|255] ""  PC
 SG_ D2P_WriteOK_Byte3_42 : 24|8@1+ (1,0) [0|255] ""  PC
 SG_ D2P_WriteOK_Byte4_42 : 32|8@1+ (1,0) [0|255] ""  PC
 SG_ D2P_WriteOK_Byte5_42 : 40|8@1+ (1,0) [0|255] ""  PC
 SG_ D2P_WriteOK_Byte6_42 : 48|8@1+ (1,0) [0|255] ""  PC
 SG_ D2P_WriteOK_Byte7_42 : 56|8@1+ (1,0) [0|255] ""  PC

BO_ 2500193899 D2P_WriteOK__43: 8 DCDC
 SG_ D2P_WriteOK_Byte0_43 : 0|8@1+ (1,0) [0|255] ""  PC
 SG_ D2P_WriteOK_Byte1_43 : 8|8@1+ (1,0) [0|255] ""  PC
 SG_ D2P_WriteOK_Byte2_43 : 16|8@1+ (1,0) [0|255] ""  PC
 SG_ D2P_WriteOK_Byte3_43 : 24|8@1+ (1,0) [0|255] ""  PC
 SG_ D2P_WriteOK_Byte4_43 : 32|8@1+ (1,0) [0|255] ""  PC
 SG_ D2P_WriteOK_Byte5_43 : 40|8@1+ (1,0) [0|255] ""  PC
 SG_ D2P_WriteOK_Byte6_43 : 48|8@1+ (1,0) [0|255] ""  PC
 SG_ D2P_WriteOK_Byte7_43 : 56|8@1+ (1,0) [0|255] ""  PC

BO_ 2500193900 D2P_WriteOK__44: 8 DCDC
 SG_ D2P_WriteOK_Byte0_44 : 0|8@1+ (1,0) [0|255] ""  PC
 SG_ D2P_WriteOK_Byte1_44 : 8|8@1+ (1,0) [0|255] ""  PC
 SG_ D2P_WriteOK_Byte2_44 : 16|8@1+ (1,0) [0|255] ""  PC
 SG_ D2P_WriteOK_Byte3_44 : 24|8@1+ (1,0) [0|255] ""  PC
 SG_ D2P_WriteOK_Byte4_44 : 32|8@1+ (1,0) [0|255] ""  PC
 SG_ D2P_WriteOK_Byte5_44 : 40|8@1+ (1,0) [0|255] ""  PC
 SG_ D2P_WriteOK_Byte6_44 : 48|8@1+ (1,0) [0|255] ""  PC
 SG_ D2P_WriteOK_Byte7_44 : 56|8@1+ (1,0) [0|255] ""  PC

BO_ 2500193901 D2P_WriteOK__45: 8 DCDC
 SG_ D2P_WriteOK_Byte0_45 : 0|8@1+ (1,0) [0|255] ""  PC
 SG_ D2P_WriteOK_Byte1_45 : 8|8@1+ (1,0) [0|255] ""  PC
 SG_ D2P_WriteOK_Byte2_45 : 16|8@1+ (1,0) [0|255] ""  PC
 SG_ D2P_WriteOK_Byte3_45 : 24|8@1+ (1,0) [0|255] ""  PC
 SG_ D2P_WriteOK_Byte4_45 : 32|8@1+ (1,0) [0|255] ""  PC
 SG_ D2P_WriteOK_Byte5_45 : 40|8@1+ (1,0) [0|255] ""  PC
 SG_ D2P_WriteOK_Byte6_45 : 48|8@1+ (1,0) [0|255] ""  PC
 SG_ D2P_WriteOK_Byte7_45 : 56|8@1+ (1,0) [0|255] ""  PC

BO_ 2500193902 D2P_WriteOK__46: 8 DCDC
 SG_ D2P_WriteOK_Byte0_46 : 0|8@1+ (1,0) [0|255] ""  PC
 SG_ D2P_WriteOK_Byte1_46 : 8|8@1+ (1,0) [0|255] ""  PC
 SG_ D2P_WriteOK_Byte2_46 : 16|8@1+ (1,0) [0|255] ""  PC
 SG_ D2P_WriteOK_Byte3_46 : 24|8@1+ (1,0) [0|255] ""  PC
 SG_ D2P_WriteOK_Byte4_46 : 32|8@1+ (1,0) [0|255] ""  PC
 SG_ D2P_WriteOK_Byte5_46 : 40|8@1+ (1,0) [0|255] ""  PC
 SG_ D2P_WriteOK_Byte6_46 : 48|8@1+ (1,0) [0|255] ""  PC
 SG_ D2P_WriteOK_Byte7_46 : 56|8@1+ (1,0) [0|255] ""  PC

BO_ 2500193903 D2P_WriteOK__47: 8 DCDC
 SG_ D2P_WriteOK_Byte0_47 : 0|8@1+ (1,0) [0|255] ""  PC
 SG_ D2P_WriteOK_Byte1_47 : 8|8@1+ (1,0) [0|255] ""  PC
 SG_ D2P_WriteOK_Byte2_47 : 16|8@1+ (1,0) [0|255] ""  PC
 SG_ D2P_WriteOK_Byte3_47 : 24|8@1+ (1,0) [0|255] ""  PC
 SG_ D2P_WriteOK_Byte4_47 : 32|8@1+ (1,0) [0|255] ""  PC
 SG_ D2P_WriteOK_Byte5_47 : 40|8@1+ (1,0) [0|255] ""  PC
 SG_ D2P_WriteOK_Byte6_47 : 48|8@1+ (1,0) [0|255] ""  PC
 SG_ D2P_WriteOK_Byte7_47 : 56|8@1+ (1,0) [0|255] ""  PC

BO_ 2500193904 D2P_WriteOK__48: 8 DCDC
 SG_ D2P_WriteOK_Byte0_48 : 0|8@1+ (1,0) [0|255] ""  PC
 SG_ D2P_WriteOK_Byte1_48 : 8|8@1+ (1,0) [0|255] ""  PC
 SG_ D2P_WriteOK_Byte2_48 : 16|8@1+ (1,0) [0|255] ""  PC
 SG_ D2P_WriteOK_Byte3_48 : 24|8@1+ (1,0) [0|255] ""  PC
 SG_ D2P_WriteOK_Byte4_48 : 32|8@1+ (1,0) [0|255] ""  PC
 SG_ D2P_WriteOK_Byte5_48 : 40|8@1+ (1,0) [0|255] ""  PC
 SG_ D2P_WriteOK_Byte6_48 : 48|8@1+ (1,0) [0|255] ""  PC
 SG_ D2P_WriteOK_Byte7_48 : 56|8@1+ (1,0) [0|255] ""  PC

BO_ 2500193905 D2P_WriteOK__49: 8 DCDC
 SG_ D2P_WriteOK_Byte0_49 : 0|8@1+ (1,0) [0|255] ""  PC
 SG_ D2P_WriteOK_Byte1_49 : 8|8@1+ (1,0) [0|255] ""  PC
 SG_ D2P_WriteOK_Byte2_49 : 16|8@1+ (1,0) [0|255] ""  PC
 SG_ D2P_WriteOK_Byte3_49 : 24|8@1+ (1,0) [0|255] ""  PC
 SG_ D2P_WriteOK_Byte4_49 : 32|8@1+ (1,0) [0|255] ""  PC
 SG_ D2P_WriteOK_Byte5_49 : 40|8@1+ (1,0) [0|255] ""  PC
 SG_ D2P_WriteOK_Byte6_49 : 48|8@1+ (1,0) [0|255] ""  PC
 SG_ D2P_WriteOK_Byte7_49 : 56|8@1+ (1,0) [0|255] ""  PC

BO_ 2500193906 D2P_WriteOK__50: 8 DCDC
 SG_ D2P_WriteOK_Byte0_50 : 0|8@1+ (1,0) [0|255] ""  PC
 SG_ D2P_WriteOK_Byte1_50 : 8|8@1+ (1,0) [0|255] ""  PC
 SG_ D2P_WriteOK_Byte2_50 : 16|8@1+ (1,0) [0|255] ""  PC
 SG_ D2P_WriteOK_Byte3_50 : 24|8@1+ (1,0) [0|255] ""  PC
 SG_ D2P_WriteOK_Byte4_50 : 32|8@1+ (1,0) [0|255] ""  PC
 SG_ D2P_WriteOK_Byte5_50 : 40|8@1+ (1,0) [0|255] ""  PC
 SG_ D2P_WriteOK_Byte6_50 : 48|8@1+ (1,0) [0|255] ""  PC
 SG_ D2P_WriteOK_Byte7_50 : 56|8@1+ (1,0) [0|255] ""  PC

BO_ 2500193907 D2P_WriteOK__51: 8 DCDC
 SG_ D2P_WriteOK_Byte0_51 : 0|8@1+ (1,0) [0|255] ""  PC
 SG_ D2P_WriteOK_Byte1_51 : 8|8@1+ (1,0) [0|255] ""  PC
 SG_ D2P_WriteOK_Byte2_51 : 16|8@1+ (1,0) [0|255] ""  PC
 SG_ D2P_WriteOK_Byte3_51 : 24|8@1+ (1,0) [0|255] ""  PC
 SG_ D2P_WriteOK_Byte4_51 : 32|8@1+ (1,0) [0|255] ""  PC
 SG_ D2P_WriteOK_Byte5_51 : 40|8@1+ (1,0) [0|255] ""  PC
 SG_ D2P_WriteOK_Byte6_51 : 48|8@1+ (1,0) [0|255] ""  PC
 SG_ D2P_WriteOK_Byte7_51 : 56|8@1+ (1,0) [0|255] ""  PC

BO_ 2500193908 D2P_WriteOK__52: 8 DCDC
 SG_ D2P_WriteOK_Byte0_52 : 0|8@1+ (1,0) [0|255] ""  PC
 SG_ D2P_WriteOK_Byte1_52 : 8|8@1+ (1,0) [0|255] ""  PC
 SG_ D2P_WriteOK_Byte2_52 : 16|8@1+ (1,0) [0|255] ""  PC
 SG_ D2P_WriteOK_Byte3_52 : 24|8@1+ (1,0) [0|255] ""  PC
 SG_ D2P_WriteOK_Byte4_52 : 32|8@1+ (1,0) [0|255] ""  PC
 SG_ D2P_WriteOK_Byte5_52 : 40|8@1+ (1,0) [0|255] ""  PC
 SG_ D2P_WriteOK_Byte6_52 : 48|8@1+ (1,0) [0|255] ""  PC
 SG_ D2P_WriteOK_Byte7_52 : 56|8@1+ (1,0) [0|255] ""  PC

BO_ 2500193909 D2P_WriteOK__53: 8 DCDC
 SG_ D2P_WriteOK_Byte0_53 : 0|8@1+ (1,0) [0|255] ""  PC
 SG_ D2P_WriteOK_Byte1_53 : 8|8@1+ (1,0) [0|255] ""  PC
 SG_ D2P_WriteOK_Byte2_53 : 16|8@1+ (1,0) [0|255] ""  PC
 SG_ D2P_WriteOK_Byte3_53 : 24|8@1+ (1,0) [0|255] ""  PC
 SG_ D2P_WriteOK_Byte4_53 : 32|8@1+ (1,0) [0|255] ""  PC
 SG_ D2P_WriteOK_Byte5_53 : 40|8@1+ (1,0) [0|255] ""  PC
 SG_ D2P_WriteOK_Byte6_53 : 48|8@1+ (1,0) [0|255] ""  PC
 SG_ D2P_WriteOK_Byte7_53 : 56|8@1+ (1,0) [0|255] ""  PC

BO_ 2500193910 D2P_WriteOK__54: 8 DCDC
 SG_ D2P_WriteOK_Byte0_54 : 0|8@1+ (1,0) [0|255] ""  PC
 SG_ D2P_WriteOK_Byte1_54 : 8|8@1+ (1,0) [0|255] ""  PC
 SG_ D2P_WriteOK_Byte2_54 : 16|8@1+ (1,0) [0|255] ""  PC
 SG_ D2P_WriteOK_Byte3_54 : 24|8@1+ (1,0) [0|255] ""  PC
 SG_ D2P_WriteOK_Byte4_54 : 32|8@1+ (1,0) [0|255] ""  PC
 SG_ D2P_WriteOK_Byte5_54 : 40|8@1+ (1,0) [0|255] ""  PC
 SG_ D2P_WriteOK_Byte6_54 : 48|8@1+ (1,0) [0|255] ""  PC
 SG_ D2P_WriteOK_Byte7_54 : 56|8@1+ (1,0) [0|255] ""  PC

BO_ 2500193911 D2P_WriteOK__55: 8 DCDC
 SG_ D2P_WriteOK_Byte0_55 : 0|8@1+ (1,0) [0|255] ""  PC
 SG_ D2P_WriteOK_Byte1_55 : 8|8@1+ (1,0) [0|255] ""  PC
 SG_ D2P_WriteOK_Byte2_55 : 16|8@1+ (1,0) [0|255] ""  PC
 SG_ D2P_WriteOK_Byte3_55 : 24|8@1+ (1,0) [0|255] ""  PC
 SG_ D2P_WriteOK_Byte4_55 : 32|8@1+ (1,0) [0|255] ""  PC
 SG_ D2P_WriteOK_Byte5_55 : 40|8@1+ (1,0) [0|255] ""  PC
 SG_ D2P_WriteOK_Byte6_55 : 48|8@1+ (1,0) [0|255] ""  PC
 SG_ D2P_WriteOK_Byte7_55 : 56|8@1+ (1,0) [0|255] ""  PC

BO_ 2500193912 D2P_WriteOK__56: 8 DCDC
 SG_ D2P_WriteOK_Byte0_56 : 0|8@1+ (1,0) [0|255] ""  PC
 SG_ D2P_WriteOK_Byte1_56 : 8|8@1+ (1,0) [0|255] ""  PC
 SG_ D2P_WriteOK_Byte2_56 : 16|8@1+ (1,0) [0|255] ""  PC
 SG_ D2P_WriteOK_Byte3_56 : 24|8@1+ (1,0) [0|255] ""  PC
 SG_ D2P_WriteOK_Byte4_56 : 32|8@1+ (1,0) [0|255] ""  PC
 SG_ D2P_WriteOK_Byte5_56 : 40|8@1+ (1,0) [0|255] ""  PC
 SG_ D2P_WriteOK_Byte6_56 : 48|8@1+ (1,0) [0|255] ""  PC
 SG_ D2P_WriteOK_Byte7_56 : 56|8@1+ (1,0) [0|255] ""  PC

BO_ 2500193913 D2P_WriteOK__57: 8 DCDC
 SG_ D2P_WriteOK_Byte0_57 : 0|8@1+ (1,0) [0|255] ""  PC
 SG_ D2P_WriteOK_Byte1_57 : 8|8@1+ (1,0) [0|255] ""  PC
 SG_ D2P_WriteOK_Byte2_57 : 16|8@1+ (1,0) [0|255] ""  PC
 SG_ D2P_WriteOK_Byte3_57 : 24|8@1+ (1,0) [0|255] ""  PC
 SG_ D2P_WriteOK_Byte4_57 : 32|8@1+ (1,0) [0|255] ""  PC
 SG_ D2P_WriteOK_Byte5_57 : 40|8@1+ (1,0) [0|255] ""  PC
 SG_ D2P_WriteOK_Byte6_57 : 48|8@1+ (1,0) [0|255] ""  PC
 SG_ D2P_WriteOK_Byte7_57 : 56|8@1+ (1,0) [0|255] ""  PC

BO_ 2500193914 D2P_WriteOK__58: 8 DCDC
 SG_ D2P_WriteOK_Byte0_58 : 0|8@1+ (1,0) [0|255] ""  PC
 SG_ D2P_WriteOK_Byte1_58 : 8|8@1+ (1,0) [0|255] ""  PC
 SG_ D2P_WriteOK_Byte2_58 : 16|8@1+ (1,0) [0|255] ""  PC
 SG_ D2P_WriteOK_Byte3_58 : 24|8@1+ (1,0) [0|255] ""  PC
 SG_ D2P_WriteOK_Byte4_58 : 32|8@1+ (1,0) [0|255] ""  PC
 SG_ D2P_WriteOK_Byte5_58 : 40|8@1+ (1,0) [0|255] ""  PC
 SG_ D2P_WriteOK_Byte6_58 : 48|8@1+ (1,0) [0|255] ""  PC
 SG_ D2P_WriteOK_Byte7_58 : 56|8@1+ (1,0) [0|255] ""  PC

BO_ 2500193915 D2P_WriteOK__59: 8 DCDC
 SG_ D2P_WriteOK_Byte0_59 : 0|8@1+ (1,0) [0|255] ""  PC
 SG_ D2P_WriteOK_Byte1_59 : 8|8@1+ (1,0) [0|255] ""  PC
 SG_ D2P_WriteOK_Byte2_59 : 16|8@1+ (1,0) [0|255] ""  PC
 SG_ D2P_WriteOK_Byte3_59 : 24|8@1+ (1,0) [0|255] ""  PC
 SG_ D2P_WriteOK_Byte4_59 : 32|8@1+ (1,0) [0|255] ""  PC
 SG_ D2P_WriteOK_Byte5_59 : 40|8@1+ (1,0) [0|255] ""  PC
 SG_ D2P_WriteOK_Byte6_59 : 48|8@1+ (1,0) [0|255] ""  PC
 SG_ D2P_WriteOK_Byte7_59 : 56|8@1+ (1,0) [0|255] ""  PC

BO_ 2500193916 D2P_WriteOK__60: 8 DCDC
 SG_ D2P_WriteOK_Byte0_60 : 0|8@1+ (1,0) [0|255] ""  PC
 SG_ D2P_WriteOK_Byte1_60 : 8|8@1+ (1,0) [0|255] ""  PC
 SG_ D2P_WriteOK_Byte2_60 : 16|8@1+ (1,0) [0|255] ""  PC
 SG_ D2P_WriteOK_Byte3_60 : 24|8@1+ (1,0) [0|255] ""  PC
 SG_ D2P_WriteOK_Byte4_60 : 32|8@1+ (1,0) [0|255] ""  PC
 SG_ D2P_WriteOK_Byte5_60 : 40|8@1+ (1,0) [0|255] ""  PC
 SG_ D2P_WriteOK_Byte6_60 : 48|8@1+ (1,0) [0|255] ""  PC
 SG_ D2P_WriteOK_Byte7_60 : 56|8@1+ (1,0) [0|255] ""  PC

BO_ 2500193917 D2P_WriteOK__61: 8 DCDC
 SG_ D2P_WriteOK_Byte0_61 : 0|8@1+ (1,0) [0|255] ""  PC
 SG_ D2P_WriteOK_Byte1_61 : 8|8@1+ (1,0) [0|255] ""  PC
 SG_ D2P_WriteOK_Byte2_61 : 16|8@1+ (1,0) [0|255] ""  PC
 SG_ D2P_WriteOK_Byte3_61 : 24|8@1+ (1,0) [0|255] ""  PC
 SG_ D2P_WriteOK_Byte4_61 : 32|8@1+ (1,0) [0|255] ""  PC
 SG_ D2P_WriteOK_Byte5_61 : 40|8@1+ (1,0) [0|255] ""  PC
 SG_ D2P_WriteOK_Byte6_61 : 48|8@1+ (1,0) [0|255] ""  PC
 SG_ D2P_WriteOK_Byte7_61 : 56|8@1+ (1,0) [0|255] ""  PC

BO_ 2500193918 D2P_WriteOK__62: 8 DCDC
 SG_ D2P_WriteOK_Byte0_62 : 0|8@1+ (1,0) [0|255] ""  PC
 SG_ D2P_WriteOK_Byte1_62 : 8|8@1+ (1,0) [0|255] ""  PC
 SG_ D2P_WriteOK_Byte2_62 : 16|8@1+ (1,0) [0|255] ""  PC
 SG_ D2P_WriteOK_Byte3_62 : 24|8@1+ (1,0) [0|255] ""  PC
 SG_ D2P_WriteOK_Byte4_62 : 32|8@1+ (1,0) [0|255] ""  PC
 SG_ D2P_WriteOK_Byte5_62 : 40|8@1+ (1,0) [0|255] ""  PC
 SG_ D2P_WriteOK_Byte6_62 : 48|8@1+ (1,0) [0|255] ""  PC
 SG_ D2P_WriteOK_Byte7_62 : 56|8@1+ (1,0) [0|255] ""  PC

BO_ 2500193919 D2P_WriteOK__63: 8 DCDC
 SG_ D2P_WriteOK_Byte0_63 : 0|8@1+ (1,0) [0|255] ""  PC
 SG_ D2P_WriteOK_Byte1_63 : 8|8@1+ (1,0) [0|255] ""  PC
 SG_ D2P_WriteOK_Byte2_63 : 16|8@1+ (1,0) [0|255] ""  PC
 SG_ D2P_WriteOK_Byte3_63 : 24|8@1+ (1,0) [0|255] ""  PC
 SG_ D2P_WriteOK_Byte4_63 : 32|8@1+ (1,0) [0|255] ""  PC
 SG_ D2P_WriteOK_Byte5_63 : 40|8@1+ (1,0) [0|255] ""  PC
 SG_ D2P_WriteOK_Byte6_63 : 48|8@1+ (1,0) [0|255] ""  PC
 SG_ D2P_WriteOK_Byte7_63 : 56|8@1+ (1,0) [0|255] ""  PC

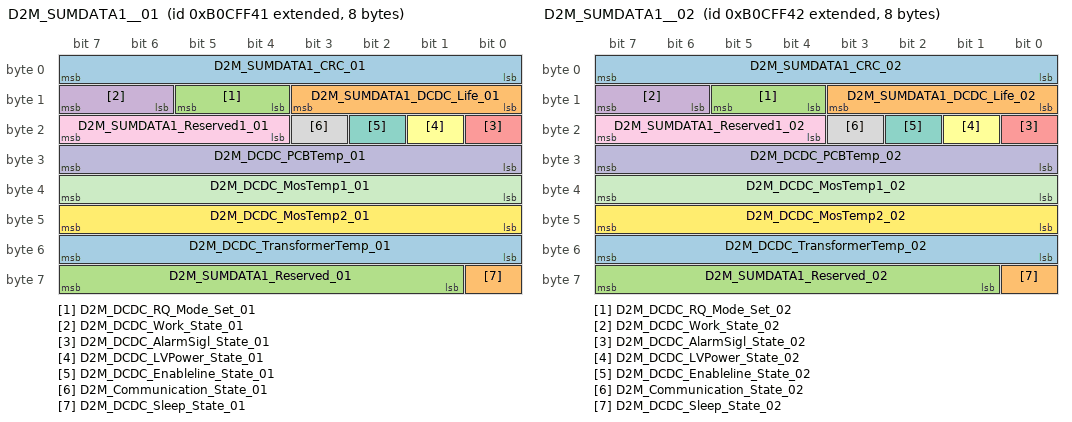
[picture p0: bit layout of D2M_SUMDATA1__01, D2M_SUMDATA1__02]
BO_ 2332884801 D2M_SUMDATA1__01: 8 DCDC
 SG_ D2M_SUMDATA1_CRC_01 : 0|8@1+ (1,0) [0|255] ""  MBMU,PC
 SG_ D2M_SUMDATA1_DCDC_Life_01 : 8|4@1+ (1,0) [0|15] ""  MBMU,PC
 SG_ D2M_DCDC_RQ_Mode_Set_01 : 12|2@1+ (1,0) [0|3] ""  MBMU,PC
 SG_ D2M_DCDC_Work_State_01 : 14|2@1+ (1,0) [0|3] ""  MBMU,PC
 SG_ D2M_DCDC_AlarmSigl_State_01 : 16|1@1+ (1,0) [0|1] ""  MBMU,PC
 SG_ D2M_DCDC_LVPower_State_01 : 17|1@1+ (1,0) [0|1] ""  MBMU,PC
 SG_ D2M_DCDC_Enableline_State_01 : 18|1@1+ (1,0) [0|1] ""  MBMU,PC
 SG_ D2M_Communication_State_01 : 19|1@1+ (1,0) [0|1] ""  MBMU,PC
 SG_ D2M_SUMDATA1_Reserved1_01 : 20|4@1+ (1,0) [0|15] ""  MBMU,PC
 SG_ D2M_DCDC_PCBTemp_01 : 24|8@1+ (1,-40) [-40|215] "℃"  MBMU,PC
 SG_ D2M_DCDC_MosTemp1_01 : 32|8@1+ (1,-40) [-40|215] "℃"  MBMU,PC
 SG_ D2M_DCDC_MosTemp2_01 : 40|8@1+ (1,-40) [-40|215] "℃"  MBMU,PC
 SG_ D2M_DCDC_TransformerTemp_01 : 48|8@1+ (1,-40) [-40|215] "℃"  MBMU,PC
 SG_ D2M_DCDC_Sleep_State_01 : 56|1@1+ (1,0) [0|1] ""  MBMU,PC
 SG_ D2M_SUMDATA1_Reserved_01 : 57|7@1+ (1,0) [0|127] ""  MBMU,PC

BO_ 2332884802 D2M_SUMDATA1__02: 8 DCDC
 SG_ D2M_SUMDATA1_CRC_02 : 0|8@1+ (1,0) [0|255] ""  MBMU,PC
 SG_ D2M_SUMDATA1_DCDC_Life_02 : 8|4@1+ (1,0) [0|15] ""  MBMU,PC
 SG_ D2M_DCDC_RQ_Mode_Set_02 : 12|2@1+ (1,0) [0|3] ""  MBMU,PC
 SG_ D2M_DCDC_Work_State_02 : 14|2@1+ (1,0) [0|3] ""  MBMU,PC
 SG_ D2M_DCDC_AlarmSigl_State_02 : 16|1@1+ (1,0) [0|1] ""  MBMU,PC
 SG_ D2M_DCDC_LVPower_State_02 : 17|1@1+ (1,0) [0|1] ""  MBMU,PC
 SG_ D2M_DCDC_Enableline_State_02 : 18|1@1+ (1,0) [0|1] ""  MBMU,PC
 SG_ D2M_Communication_State_02 : 19|1@1+ (1,0) [0|1] ""  MBMU,PC
 SG_ D2M_SUMDATA1_Reserved1_02 : 20|4@1+ (1,0) [0|15] ""  MBMU,PC
 SG_ D2M_DCDC_PCBTemp_02 : 24|8@1+ (1,-40) [-40|215] "℃"  MBMU,PC
 SG_ D2M_DCDC_MosTemp1_02 : 32|8@1+ (1,-40) [-40|215] "℃"  MBMU,PC
 SG_ D2M_DCDC_MosTemp2_02 : 40|8@1+ (1,-40) [-40|215] "℃"  MBMU,PC
 SG_ D2M_DCDC_TransformerTemp_02 : 48|8@1+ (1,-40) [-40|215] "℃"  MBMU,PC
 SG_ D2M_DCDC_Sleep_State_02 : 56|1@1+ (1,0) [0|1] ""  MBMU,PC
 SG_ D2M_SUMDATA1_Reserved_02 : 57|7@1+ (1,0) [0|127] ""  MBMU,PC

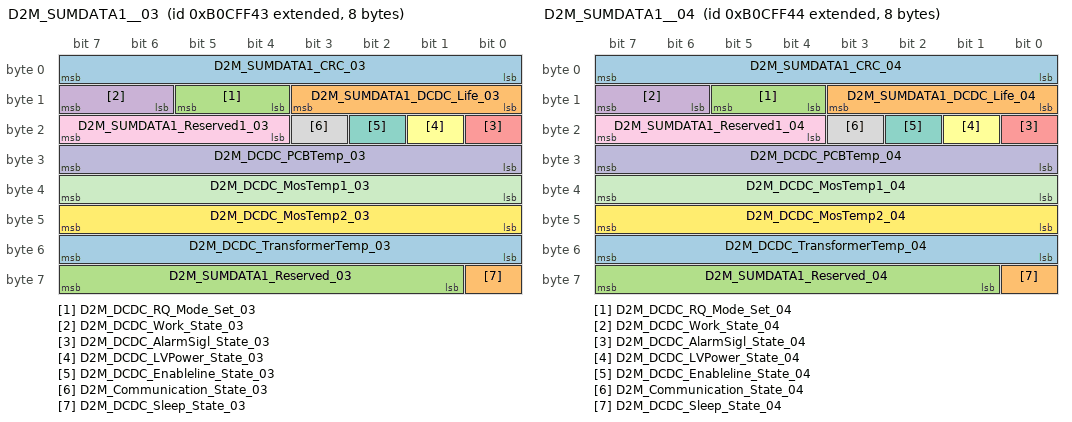
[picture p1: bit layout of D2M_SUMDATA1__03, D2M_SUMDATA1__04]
BO_ 2332884803 D2M_SUMDATA1__03: 8 DCDC
 SG_ D2M_SUMDATA1_CRC_03 : 0|8@1+ (1,0) [0|255] ""  MBMU,PC
 SG_ D2M_SUMDATA1_DCDC_Life_03 : 8|4@1+ (1,0) [0|15] ""  MBMU,PC
 SG_ D2M_DCDC_RQ_Mode_Set_03 : 12|2@1+ (1,0) [0|3] ""  MBMU,PC
 SG_ D2M_DCDC_Work_State_03 : 14|2@1+ (1,0) [0|3] ""  MBMU,PC
 SG_ D2M_DCDC_AlarmSigl_State_03 : 16|1@1+ (1,0) [0|1] ""  MBMU,PC
 SG_ D2M_DCDC_LVPower_State_03 : 17|1@1+ (1,0) [0|1] ""  MBMU,PC
 SG_ D2M_DCDC_Enableline_State_03 : 18|1@1+ (1,0) [0|1] ""  MBMU,PC
 SG_ D2M_Communication_State_03 : 19|1@1+ (1,0) [0|1] ""  MBMU,PC
 SG_ D2M_SUMDATA1_Reserved1_03 : 20|4@1+ (1,0) [0|15] ""  MBMU,PC
 SG_ D2M_DCDC_PCBTemp_03 : 24|8@1+ (1,-40) [-40|215] "℃"  MBMU,PC
 SG_ D2M_DCDC_MosTemp1_03 : 32|8@1+ (1,-40) [-40|215] "℃"  MBMU,PC
 SG_ D2M_DCDC_MosTemp2_03 : 40|8@1+ (1,-40) [-40|215] "℃"  MBMU,PC
 SG_ D2M_DCDC_TransformerTemp_03 : 48|8@1+ (1,-40) [-40|215] "℃"  MBMU,PC
 SG_ D2M_DCDC_Sleep_State_03 : 56|1@1+ (1,0) [0|1] ""  MBMU,PC
 SG_ D2M_SUMDATA1_Reserved_03 : 57|7@1+ (1,0) [0|127] ""  MBMU,PC

BO_ 2332884804 D2M_SUMDATA1__04: 8 DCDC
 SG_ D2M_SUMDATA1_CRC_04 : 0|8@1+ (1,0) [0|255] ""  MBMU,PC
 SG_ D2M_SUMDATA1_DCDC_Life_04 : 8|4@1+ (1,0) [0|15] ""  MBMU,PC
 SG_ D2M_DCDC_RQ_Mode_Set_04 : 12|2@1+ (1,0) [0|3] ""  MBMU,PC
 SG_ D2M_DCDC_Work_State_04 : 14|2@1+ (1,0) [0|3] ""  MBMU,PC
 SG_ D2M_DCDC_AlarmSigl_State_04 : 16|1@1+ (1,0) [0|1] ""  MBMU,PC
 SG_ D2M_DCDC_LVPower_State_04 : 17|1@1+ (1,0) [0|1] ""  MBMU,PC
 SG_ D2M_DCDC_Enableline_State_04 : 18|1@1+ (1,0) [0|1] ""  MBMU,PC
 SG_ D2M_Communication_State_04 : 19|1@1+ (1,0) [0|1] ""  MBMU,PC
 SG_ D2M_SUMDATA1_Reserved1_04 : 20|4@1+ (1,0) [0|15] ""  MBMU,PC
 SG_ D2M_DCDC_PCBTemp_04 : 24|8@1+ (1,-40) [-40|215] "℃"  MBMU,PC
 SG_ D2M_DCDC_MosTemp1_04 : 32|8@1+ (1,-40) [-40|215] "℃"  MBMU,PC
 SG_ D2M_DCDC_MosTemp2_04 : 40|8@1+ (1,-40) [-40|215] "℃"  MBMU,PC
 SG_ D2M_DCDC_TransformerTemp_04 : 48|8@1+ (1,-40) [-40|215] "℃"  MBMU,PC
 SG_ D2M_DCDC_Sleep_State_04 : 56|1@1+ (1,0) [0|1] ""  MBMU,PC
 SG_ D2M_SUMDATA1_Reserved_04 : 57|7@1+ (1,0) [0|127] ""  MBMU,PC

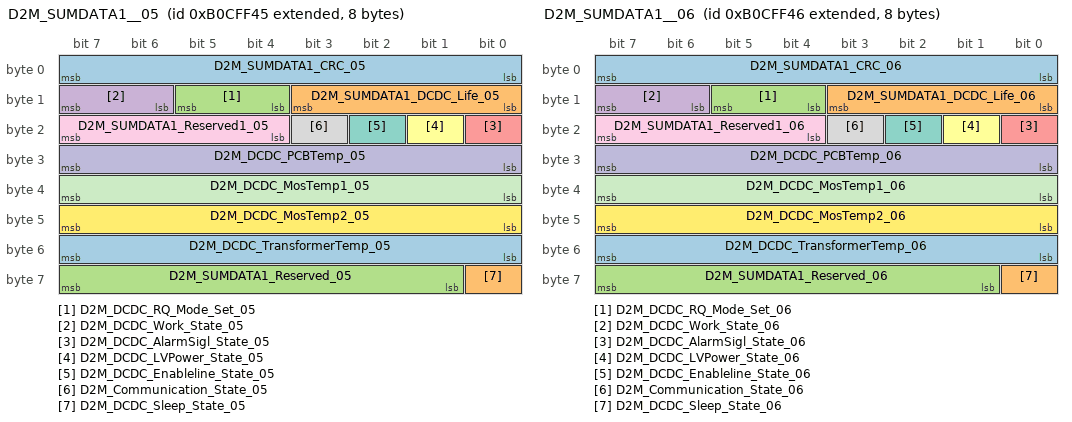
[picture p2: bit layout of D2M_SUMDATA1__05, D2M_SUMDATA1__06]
BO_ 2332884805 D2M_SUMDATA1__05: 8 DCDC
 SG_ D2M_SUMDATA1_CRC_05 : 0|8@1+ (1,0) [0|255] ""  MBMU,PC
 SG_ D2M_SUMDATA1_DCDC_Life_05 : 8|4@1+ (1,0) [0|15] ""  MBMU,PC
 SG_ D2M_DCDC_RQ_Mode_Set_05 : 12|2@1+ (1,0) [0|3] ""  MBMU,PC
 SG_ D2M_DCDC_Work_State_05 : 14|2@1+ (1,0) [0|3] ""  MBMU,PC
 SG_ D2M_DCDC_AlarmSigl_State_05 : 16|1@1+ (1,0) [0|1] ""  MBMU,PC
 SG_ D2M_DCDC_LVPower_State_05 : 17|1@1+ (1,0) [0|1] ""  MBMU,PC
 SG_ D2M_DCDC_Enableline_State_05 : 18|1@1+ (1,0) [0|1] ""  MBMU,PC
 SG_ D2M_Communication_State_05 : 19|1@1+ (1,0) [0|1] ""  MBMU,PC
 SG_ D2M_SUMDATA1_Reserved1_05 : 20|4@1+ (1,0) [0|15] ""  MBMU,PC
 SG_ D2M_DCDC_PCBTemp_05 : 24|8@1+ (1,-40) [-40|215] "℃"  MBMU,PC
 SG_ D2M_DCDC_MosTemp1_05 : 32|8@1+ (1,-40) [-40|215] "℃"  MBMU,PC
 SG_ D2M_DCDC_MosTemp2_05 : 40|8@1+ (1,-40) [-40|215] "℃"  MBMU,PC
 SG_ D2M_DCDC_TransformerTemp_05 : 48|8@1+ (1,-40) [-40|215] "℃"  MBMU,PC
 SG_ D2M_DCDC_Sleep_State_05 : 56|1@1+ (1,0) [0|1] ""  MBMU,PC
 SG_ D2M_SUMDATA1_Reserved_05 : 57|7@1+ (1,0) [0|127] ""  MBMU,PC

BO_ 2332884806 D2M_SUMDATA1__06: 8 DCDC
 SG_ D2M_SUMDATA1_CRC_06 : 0|8@1+ (1,0) [0|255] ""  MBMU,PC
 SG_ D2M_SUMDATA1_DCDC_Life_06 : 8|4@1+ (1,0) [0|15] ""  MBMU,PC
 SG_ D2M_DCDC_RQ_Mode_Set_06 : 12|2@1+ (1,0) [0|3] ""  MBMU,PC
 SG_ D2M_DCDC_Work_State_06 : 14|2@1+ (1,0) [0|3] ""  MBMU,PC
 SG_ D2M_DCDC_AlarmSigl_State_06 : 16|1@1+ (1,0) [0|1] ""  MBMU,PC
 SG_ D2M_DCDC_LVPower_State_06 : 17|1@1+ (1,0) [0|1] ""  MBMU,PC
 SG_ D2M_DCDC_Enableline_State_06 : 18|1@1+ (1,0) [0|1] ""  MBMU,PC
 SG_ D2M_Communication_State_06 : 19|1@1+ (1,0) [0|1] ""  MBMU,PC
 SG_ D2M_SUMDATA1_Reserved1_06 : 20|4@1+ (1,0) [0|15] ""  MBMU,PC
 SG_ D2M_DCDC_PCBTemp_06 : 24|8@1+ (1,-40) [-40|215] "℃"  MBMU,PC
 SG_ D2M_DCDC_MosTemp1_06 : 32|8@1+ (1,-40) [-40|215] "℃"  MBMU,PC
 SG_ D2M_DCDC_MosTemp2_06 : 40|8@1+ (1,-40) [-40|215] "℃"  MBMU,PC
 SG_ D2M_DCDC_TransformerTemp_06 : 48|8@1+ (1,-40) [-40|215] "℃"  MBMU,PC
 SG_ D2M_DCDC_Sleep_State_06 : 56|1@1+ (1,0) [0|1] ""  MBMU,PC
 SG_ D2M_SUMDATA1_Reserved_06 : 57|7@1+ (1,0) [0|127] ""  MBMU,PC

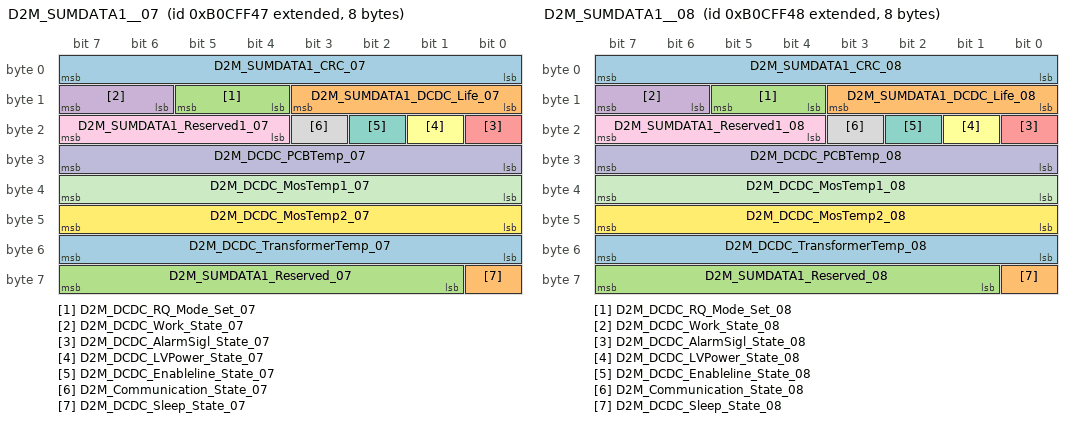
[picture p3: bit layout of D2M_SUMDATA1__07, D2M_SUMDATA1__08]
BO_ 2332884807 D2M_SUMDATA1__07: 8 DCDC
 SG_ D2M_SUMDATA1_CRC_07 : 0|8@1+ (1,0) [0|255] ""  MBMU,PC
 SG_ D2M_SUMDATA1_DCDC_Life_07 : 8|4@1+ (1,0) [0|15] ""  MBMU,PC
 SG_ D2M_DCDC_RQ_Mode_Set_07 : 12|2@1+ (1,0) [0|3] ""  MBMU,PC
 SG_ D2M_DCDC_Work_State_07 : 14|2@1+ (1,0) [0|3] ""  MBMU,PC
 SG_ D2M_DCDC_AlarmSigl_State_07 : 16|1@1+ (1,0) [0|1] ""  MBMU,PC
 SG_ D2M_DCDC_LVPower_State_07 : 17|1@1+ (1,0) [0|1] ""  MBMU,PC
 SG_ D2M_DCDC_Enableline_State_07 : 18|1@1+ (1,0) [0|1] ""  MBMU,PC
 SG_ D2M_Communication_State_07 : 19|1@1+ (1,0) [0|1] ""  MBMU,PC
 SG_ D2M_SUMDATA1_Reserved1_07 : 20|4@1+ (1,0) [0|15] ""  MBMU,PC
 SG_ D2M_DCDC_PCBTemp_07 : 24|8@1+ (1,-40) [-40|215] "℃"  MBMU,PC
 SG_ D2M_DCDC_MosTemp1_07 : 32|8@1+ (1,-40) [-40|215] "℃"  MBMU,PC
 SG_ D2M_DCDC_MosTemp2_07 : 40|8@1+ (1,-40) [-40|215] "℃"  MBMU,PC
 SG_ D2M_DCDC_TransformerTemp_07 : 48|8@1+ (1,-40) [-40|215] "℃"  MBMU,PC
 SG_ D2M_DCDC_Sleep_State_07 : 56|1@1+ (1,0) [0|1] ""  MBMU,PC
 SG_ D2M_SUMDATA1_Reserved_07 : 57|7@1+ (1,0) [0|127] ""  MBMU,PC

BO_ 2332884808 D2M_SUMDATA1__08: 8 DCDC
 SG_ D2M_SUMDATA1_CRC_08 : 0|8@1+ (1,0) [0|255] ""  MBMU,PC
 SG_ D2M_SUMDATA1_DCDC_Life_08 : 8|4@1+ (1,0) [0|15] ""  MBMU,PC
 SG_ D2M_DCDC_RQ_Mode_Set_08 : 12|2@1+ (1,0) [0|3] ""  MBMU,PC
 SG_ D2M_DCDC_Work_State_08 : 14|2@1+ (1,0) [0|3] ""  MBMU,PC
 SG_ D2M_DCDC_AlarmSigl_State_08 : 16|1@1+ (1,0) [0|1] ""  MBMU,PC
 SG_ D2M_DCDC_LVPower_State_08 : 17|1@1+ (1,0) [0|1] ""  MBMU,PC
 SG_ D2M_DCDC_Enableline_State_08 : 18|1@1+ (1,0) [0|1] ""  MBMU,PC
 SG_ D2M_Communication_State_08 : 19|1@1+ (1,0) [0|1] ""  MBMU,PC
 SG_ D2M_SUMDATA1_Reserved1_08 : 20|4@1+ (1,0) [0|15] ""  MBMU,PC
 SG_ D2M_DCDC_PCBTemp_08 : 24|8@1+ (1,-40) [-40|215] "℃"  MBMU,PC
 SG_ D2M_DCDC_MosTemp1_08 : 32|8@1+ (1,-40) [-40|215] "℃"  MBMU,PC
 SG_ D2M_DCDC_MosTemp2_08 : 40|8@1+ (1,-40) [-40|215] "℃"  MBMU,PC
 SG_ D2M_DCDC_TransformerTemp_08 : 48|8@1+ (1,-40) [-40|215] "℃"  MBMU,PC
 SG_ D2M_DCDC_Sleep_State_08 : 56|1@1+ (1,0) [0|1] ""  MBMU,PC
 SG_ D2M_SUMDATA1_Reserved_08 : 57|7@1+ (1,0) [0|127] ""  MBMU,PC

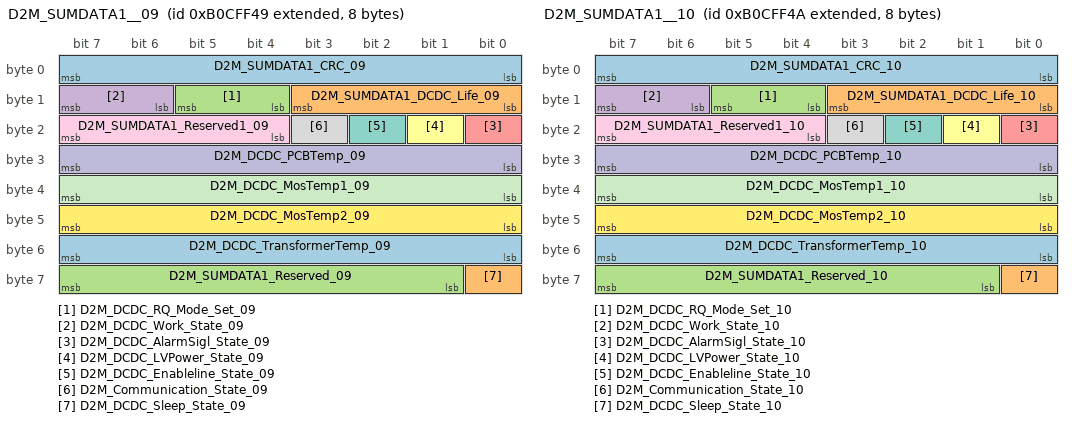
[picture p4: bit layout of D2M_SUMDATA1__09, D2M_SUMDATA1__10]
BO_ 2332884809 D2M_SUMDATA1__09: 8 DCDC
 SG_ D2M_SUMDATA1_CRC_09 : 0|8@1+ (1,0) [0|255] ""  MBMU,PC
 SG_ D2M_SUMDATA1_DCDC_Life_09 : 8|4@1+ (1,0) [0|15] ""  MBMU,PC
 SG_ D2M_DCDC_RQ_Mode_Set_09 : 12|2@1+ (1,0) [0|3] ""  MBMU,PC
 SG_ D2M_DCDC_Work_State_09 : 14|2@1+ (1,0) [0|3] ""  MBMU,PC
 SG_ D2M_DCDC_AlarmSigl_State_09 : 16|1@1+ (1,0) [0|1] ""  MBMU,PC
 SG_ D2M_DCDC_LVPower_State_09 : 17|1@1+ (1,0) [0|1] ""  MBMU,PC
 SG_ D2M_DCDC_Enableline_State_09 : 18|1@1+ (1,0) [0|1] ""  MBMU,PC
 SG_ D2M_Communication_State_09 : 19|1@1+ (1,0) [0|1] ""  MBMU,PC
 SG_ D2M_SUMDATA1_Reserved1_09 : 20|4@1+ (1,0) [0|15] ""  MBMU,PC
 SG_ D2M_DCDC_PCBTemp_09 : 24|8@1+ (1,-40) [-40|215] "℃"  MBMU,PC
 SG_ D2M_DCDC_MosTemp1_09 : 32|8@1+ (1,-40) [-40|215] "℃"  MBMU,PC
 SG_ D2M_DCDC_MosTemp2_09 : 40|8@1+ (1,-40) [-40|215] "℃"  MBMU,PC
 SG_ D2M_DCDC_TransformerTemp_09 : 48|8@1+ (1,-40) [-40|215] "℃"  MBMU,PC
 SG_ D2M_DCDC_Sleep_State_09 : 56|1@1+ (1,0) [0|1] ""  MBMU,PC
 SG_ D2M_SUMDATA1_Reserved_09 : 57|7@1+ (1,0) [0|127] ""  MBMU,PC

BO_ 2332884810 D2M_SUMDATA1__10: 8 DCDC
 SG_ D2M_SUMDATA1_CRC_10 : 0|8@1+ (1,0) [0|255] ""  MBMU,PC
 SG_ D2M_SUMDATA1_DCDC_Life_10 : 8|4@1+ (1,0) [0|15] ""  MBMU,PC
 SG_ D2M_DCDC_RQ_Mode_Set_10 : 12|2@1+ (1,0) [0|3] ""  MBMU,PC
 SG_ D2M_DCDC_Work_State_10 : 14|2@1+ (1,0) [0|3] ""  MBMU,PC
 SG_ D2M_DCDC_AlarmSigl_State_10 : 16|1@1+ (1,0) [0|1] ""  MBMU,PC
 SG_ D2M_DCDC_LVPower_State_10 : 17|1@1+ (1,0) [0|1] ""  MBMU,PC
 SG_ D2M_DCDC_Enableline_State_10 : 18|1@1+ (1,0) [0|1] ""  MBMU,PC
 SG_ D2M_Communication_State_10 : 19|1@1+ (1,0) [0|1] ""  MBMU,PC
 SG_ D2M_SUMDATA1_Reserved1_10 : 20|4@1+ (1,0) [0|15] ""  MBMU,PC
 SG_ D2M_DCDC_PCBTemp_10 : 24|8@1+ (1,-40) [-40|215] "℃"  MBMU,PC
 SG_ D2M_DCDC_MosTemp1_10 : 32|8@1+ (1,-40) [-40|215] "℃"  MBMU,PC
 SG_ D2M_DCDC_MosTemp2_10 : 40|8@1+ (1,-40) [-40|215] "℃"  MBMU,PC
 SG_ D2M_DCDC_TransformerTemp_10 : 48|8@1+ (1,-40) [-40|215] "℃"  MBMU,PC
 SG_ D2M_DCDC_Sleep_State_10 : 56|1@1+ (1,0) [0|1] ""  MBMU,PC
 SG_ D2M_SUMDATA1_Reserved_10 : 57|7@1+ (1,0) [0|127] ""  MBMU,PC

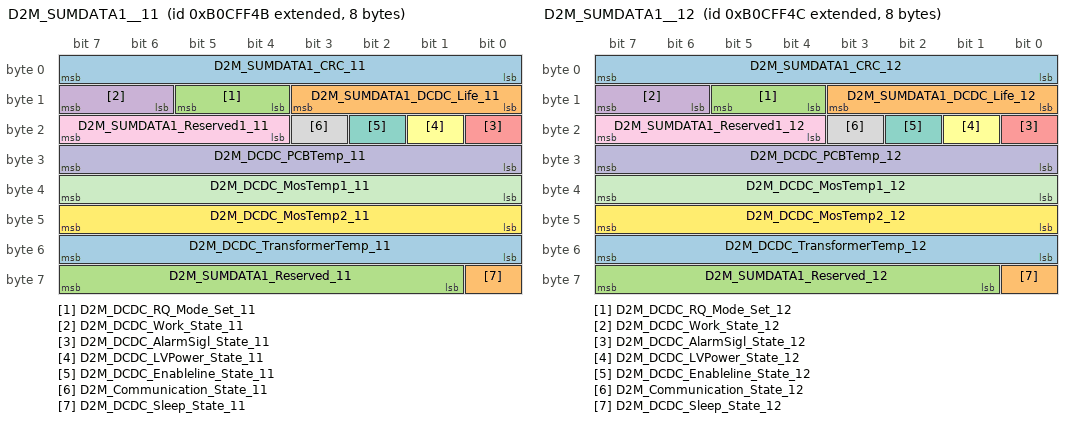
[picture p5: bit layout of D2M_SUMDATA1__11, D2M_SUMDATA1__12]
BO_ 2332884811 D2M_SUMDATA1__11: 8 DCDC
 SG_ D2M_SUMDATA1_CRC_11 : 0|8@1+ (1,0) [0|255] ""  MBMU,PC
 SG_ D2M_SUMDATA1_DCDC_Life_11 : 8|4@1+ (1,0) [0|15] ""  MBMU,PC
 SG_ D2M_DCDC_RQ_Mode_Set_11 : 12|2@1+ (1,0) [0|3] ""  MBMU,PC
 SG_ D2M_DCDC_Work_State_11 : 14|2@1+ (1,0) [0|3] ""  MBMU,PC
 SG_ D2M_DCDC_AlarmSigl_State_11 : 16|1@1+ (1,0) [0|1] ""  MBMU,PC
 SG_ D2M_DCDC_LVPower_State_11 : 17|1@1+ (1,0) [0|1] ""  MBMU,PC
 SG_ D2M_DCDC_Enableline_State_11 : 18|1@1+ (1,0) [0|1] ""  MBMU,PC
 SG_ D2M_Communication_State_11 : 19|1@1+ (1,0) [0|1] ""  MBMU,PC
 SG_ D2M_SUMDATA1_Reserved1_11 : 20|4@1+ (1,0) [0|15] ""  MBMU,PC
 SG_ D2M_DCDC_PCBTemp_11 : 24|8@1+ (1,-40) [-40|215] "℃"  MBMU,PC
 SG_ D2M_DCDC_MosTemp1_11 : 32|8@1+ (1,-40) [-40|215] "℃"  MBMU,PC
 SG_ D2M_DCDC_MosTemp2_11 : 40|8@1+ (1,-40) [-40|215] "℃"  MBMU,PC
 SG_ D2M_DCDC_TransformerTemp_11 : 48|8@1+ (1,-40) [-40|215] "℃"  MBMU,PC
 SG_ D2M_DCDC_Sleep_State_11 : 56|1@1+ (1,0) [0|1] ""  MBMU,PC
 SG_ D2M_SUMDATA1_Reserved_11 : 57|7@1+ (1,0) [0|127] ""  MBMU,PC

BO_ 2332884812 D2M_SUMDATA1__12: 8 DCDC
 SG_ D2M_SUMDATA1_CRC_12 : 0|8@1+ (1,0) [0|255] ""  MBMU,PC
 SG_ D2M_SUMDATA1_DCDC_Life_12 : 8|4@1+ (1,0) [0|15] ""  MBMU,PC
 SG_ D2M_DCDC_RQ_Mode_Set_12 : 12|2@1+ (1,0) [0|3] ""  MBMU,PC
 SG_ D2M_DCDC_Work_State_12 : 14|2@1+ (1,0) [0|3] ""  MBMU,PC
 SG_ D2M_DCDC_AlarmSigl_State_12 : 16|1@1+ (1,0) [0|1] ""  MBMU,PC
 SG_ D2M_DCDC_LVPower_State_12 : 17|1@1+ (1,0) [0|1] ""  MBMU,PC
 SG_ D2M_DCDC_Enableline_State_12 : 18|1@1+ (1,0) [0|1] ""  MBMU,PC
 SG_ D2M_Communication_State_12 : 19|1@1+ (1,0) [0|1] ""  MBMU,PC
 SG_ D2M_SUMDATA1_Reserved1_12 : 20|4@1+ (1,0) [0|15] ""  MBMU,PC
 SG_ D2M_DCDC_PCBTemp_12 : 24|8@1+ (1,-40) [-40|215] "℃"  MBMU,PC
 SG_ D2M_DCDC_MosTemp1_12 : 32|8@1+ (1,-40) [-40|215] "℃"  MBMU,PC
 SG_ D2M_DCDC_MosTemp2_12 : 40|8@1+ (1,-40) [-40|215] "℃"  MBMU,PC
 SG_ D2M_DCDC_TransformerTemp_12 : 48|8@1+ (1,-40) [-40|215] "℃"  MBMU,PC
 SG_ D2M_DCDC_Sleep_State_12 : 56|1@1+ (1,0) [0|1] ""  MBMU,PC
 SG_ D2M_SUMDATA1_Reserved_12 : 57|7@1+ (1,0) [0|127] ""  MBMU,PC

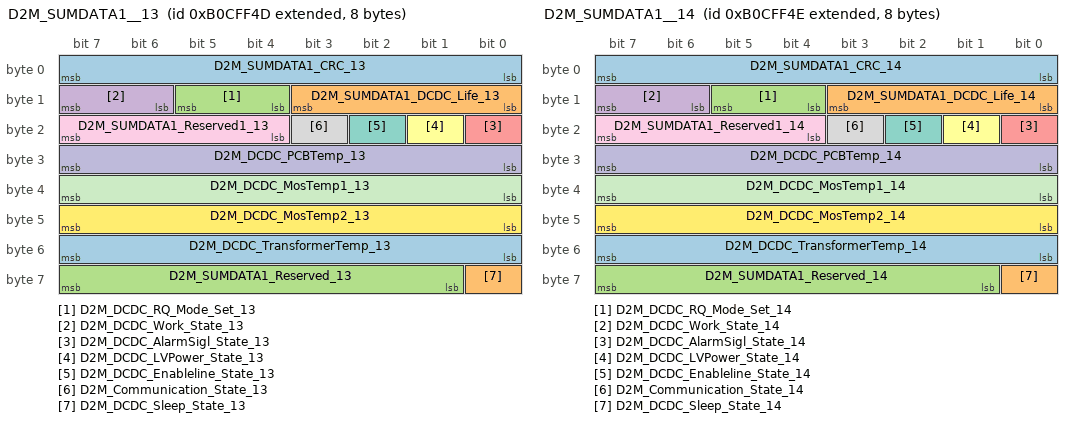
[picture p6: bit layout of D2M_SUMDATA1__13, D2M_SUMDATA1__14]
BO_ 2332884813 D2M_SUMDATA1__13: 8 DCDC
 SG_ D2M_SUMDATA1_CRC_13 : 0|8@1+ (1,0) [0|255] ""  MBMU,PC
 SG_ D2M_SUMDATA1_DCDC_Life_13 : 8|4@1+ (1,0) [0|15] ""  MBMU,PC
 SG_ D2M_DCDC_RQ_Mode_Set_13 : 12|2@1+ (1,0) [0|3] ""  MBMU,PC
 SG_ D2M_DCDC_Work_State_13 : 14|2@1+ (1,0) [0|3] ""  MBMU,PC
 SG_ D2M_DCDC_AlarmSigl_State_13 : 16|1@1+ (1,0) [0|1] ""  MBMU,PC
 SG_ D2M_DCDC_LVPower_State_13 : 17|1@1+ (1,0) [0|1] ""  MBMU,PC
 SG_ D2M_DCDC_Enableline_State_13 : 18|1@1+ (1,0) [0|1] ""  MBMU,PC
 SG_ D2M_Communication_State_13 : 19|1@1+ (1,0) [0|1] ""  MBMU,PC
 SG_ D2M_SUMDATA1_Reserved1_13 : 20|4@1+ (1,0) [0|15] ""  MBMU,PC
 SG_ D2M_DCDC_PCBTemp_13 : 24|8@1+ (1,-40) [-40|215] "℃"  MBMU,PC
 SG_ D2M_DCDC_MosTemp1_13 : 32|8@1+ (1,-40) [-40|215] "℃"  MBMU,PC
 SG_ D2M_DCDC_MosTemp2_13 : 40|8@1+ (1,-40) [-40|215] "℃"  MBMU,PC
 SG_ D2M_DCDC_TransformerTemp_13 : 48|8@1+ (1,-40) [-40|215] "℃"  MBMU,PC
 SG_ D2M_DCDC_Sleep_State_13 : 56|1@1+ (1,0) [0|1] ""  MBMU,PC
 SG_ D2M_SUMDATA1_Reserved_13 : 57|7@1+ (1,0) [0|127] ""  MBMU,PC

BO_ 2332884814 D2M_SUMDATA1__14: 8 DCDC
 SG_ D2M_SUMDATA1_CRC_14 : 0|8@1+ (1,0) [0|255] ""  MBMU,PC
 SG_ D2M_SUMDATA1_DCDC_Life_14 : 8|4@1+ (1,0) [0|15] ""  MBMU,PC
 SG_ D2M_DCDC_RQ_Mode_Set_14 : 12|2@1+ (1,0) [0|3] ""  MBMU,PC
 SG_ D2M_DCDC_Work_State_14 : 14|2@1+ (1,0) [0|3] ""  MBMU,PC
 SG_ D2M_DCDC_AlarmSigl_State_14 : 16|1@1+ (1,0) [0|1] ""  MBMU,PC
 SG_ D2M_DCDC_LVPower_State_14 : 17|1@1+ (1,0) [0|1] ""  MBMU,PC
 SG_ D2M_DCDC_Enableline_State_14 : 18|1@1+ (1,0) [0|1] ""  MBMU,PC
 SG_ D2M_Communication_State_14 : 19|1@1+ (1,0) [0|1] ""  MBMU,PC
 SG_ D2M_SUMDATA1_Reserved1_14 : 20|4@1+ (1,0) [0|15] ""  MBMU,PC
 SG_ D2M_DCDC_PCBTemp_14 : 24|8@1+ (1,-40) [-40|215] "℃"  MBMU,PC
 SG_ D2M_DCDC_MosTemp1_14 : 32|8@1+ (1,-40) [-40|215] "℃"  MBMU,PC
 SG_ D2M_DCDC_MosTemp2_14 : 40|8@1+ (1,-40) [-40|215] "℃"  MBMU,PC
 SG_ D2M_DCDC_TransformerTemp_14 : 48|8@1+ (1,-40) [-40|215] "℃"  MBMU,PC
 SG_ D2M_DCDC_Sleep_State_14 : 56|1@1+ (1,0) [0|1] ""  MBMU,PC
 SG_ D2M_SUMDATA1_Reserved_14 : 57|7@1+ (1,0) [0|127] ""  MBMU,PC

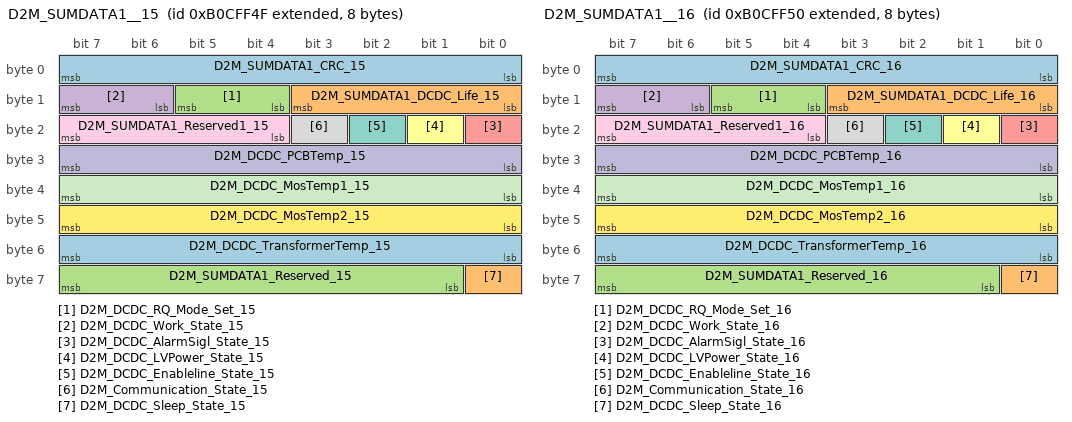
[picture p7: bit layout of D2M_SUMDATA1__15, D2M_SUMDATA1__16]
BO_ 2332884815 D2M_SUMDATA1__15: 8 DCDC
 SG_ D2M_SUMDATA1_CRC_15 : 0|8@1+ (1,0) [0|255] ""  MBMU,PC
 SG_ D2M_SUMDATA1_DCDC_Life_15 : 8|4@1+ (1,0) [0|15] ""  MBMU,PC
 SG_ D2M_DCDC_RQ_Mode_Set_15 : 12|2@1+ (1,0) [0|3] ""  MBMU,PC
 SG_ D2M_DCDC_Work_State_15 : 14|2@1+ (1,0) [0|3] ""  MBMU,PC
 SG_ D2M_DCDC_AlarmSigl_State_15 : 16|1@1+ (1,0) [0|1] ""  MBMU,PC
 SG_ D2M_DCDC_LVPower_State_15 : 17|1@1+ (1,0) [0|1] ""  MBMU,PC
 SG_ D2M_DCDC_Enableline_State_15 : 18|1@1+ (1,0) [0|1] ""  MBMU,PC
 SG_ D2M_Communication_State_15 : 19|1@1+ (1,0) [0|1] ""  MBMU,PC
 SG_ D2M_SUMDATA1_Reserved1_15 : 20|4@1+ (1,0) [0|15] ""  MBMU,PC
 SG_ D2M_DCDC_PCBTemp_15 : 24|8@1+ (1,-40) [-40|215] "℃"  MBMU,PC
 SG_ D2M_DCDC_MosTemp1_15 : 32|8@1+ (1,-40) [-40|215] "℃"  MBMU,PC
 SG_ D2M_DCDC_MosTemp2_15 : 40|8@1+ (1,-40) [-40|215] "℃"  MBMU,PC
 SG_ D2M_DCDC_TransformerTemp_15 : 48|8@1+ (1,-40) [-40|215] "℃"  MBMU,PC
 SG_ D2M_DCDC_Sleep_State_15 : 56|1@1+ (1,0) [0|1] ""  MBMU,PC
 SG_ D2M_SUMDATA1_Reserved_15 : 57|7@1+ (1,0) [0|127] ""  MBMU,PC

BO_ 2332884816 D2M_SUMDATA1__16: 8 DCDC
 SG_ D2M_SUMDATA1_CRC_16 : 0|8@1+ (1,0) [0|255] ""  MBMU,PC
 SG_ D2M_SUMDATA1_DCDC_Life_16 : 8|4@1+ (1,0) [0|15] ""  MBMU,PC
 SG_ D2M_DCDC_RQ_Mode_Set_16 : 12|2@1+ (1,0) [0|3] ""  MBMU,PC
 SG_ D2M_DCDC_Work_State_16 : 14|2@1+ (1,0) [0|3] ""  MBMU,PC
 SG_ D2M_DCDC_AlarmSigl_State_16 : 16|1@1+ (1,0) [0|1] ""  MBMU,PC
 SG_ D2M_DCDC_LVPower_State_16 : 17|1@1+ (1,0) [0|1] ""  MBMU,PC
 SG_ D2M_DCDC_Enableline_State_16 : 18|1@1+ (1,0) [0|1] ""  MBMU,PC
 SG_ D2M_Communication_State_16 : 19|1@1+ (1,0) [0|1] ""  MBMU,PC
 SG_ D2M_SUMDATA1_Reserved1_16 : 20|4@1+ (1,0) [0|15] ""  MBMU,PC
 SG_ D2M_DCDC_PCBTemp_16 : 24|8@1+ (1,-40) [-40|215] "℃"  MBMU,PC
 SG_ D2M_DCDC_MosTemp1_16 : 32|8@1+ (1,-40) [-40|215] "℃"  MBMU,PC
 SG_ D2M_DCDC_MosTemp2_16 : 40|8@1+ (1,-40) [-40|215] "℃"  MBMU,PC
 SG_ D2M_DCDC_TransformerTemp_16 : 48|8@1+ (1,-40) [-40|215] "℃"  MBMU,PC
 SG_ D2M_DCDC_Sleep_State_16 : 56|1@1+ (1,0) [0|1] ""  MBMU,PC
 SG_ D2M_SUMDATA1_Reserved_16 : 57|7@1+ (1,0) [0|127] ""  MBMU,PC

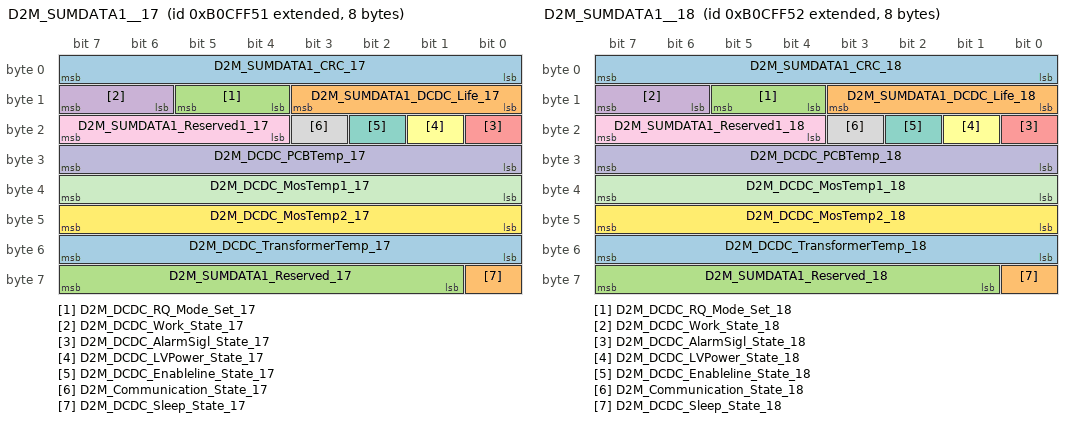
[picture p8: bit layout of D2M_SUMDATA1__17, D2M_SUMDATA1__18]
BO_ 2332884817 D2M_SUMDATA1__17: 8 DCDC
 SG_ D2M_SUMDATA1_CRC_17 : 0|8@1+ (1,0) [0|255] ""  MBMU,PC
 SG_ D2M_SUMDATA1_DCDC_Life_17 : 8|4@1+ (1,0) [0|15] ""  MBMU,PC
 SG_ D2M_DCDC_RQ_Mode_Set_17 : 12|2@1+ (1,0) [0|3] ""  MBMU,PC
 SG_ D2M_DCDC_Work_State_17 : 14|2@1+ (1,0) [0|3] ""  MBMU,PC
 SG_ D2M_DCDC_AlarmSigl_State_17 : 16|1@1+ (1,0) [0|1] ""  MBMU,PC
 SG_ D2M_DCDC_LVPower_State_17 : 17|1@1+ (1,0) [0|1] ""  MBMU,PC
 SG_ D2M_DCDC_Enableline_State_17 : 18|1@1+ (1,0) [0|1] ""  MBMU,PC
 SG_ D2M_Communication_State_17 : 19|1@1+ (1,0) [0|1] ""  MBMU,PC
 SG_ D2M_SUMDATA1_Reserved1_17 : 20|4@1+ (1,0) [0|15] ""  MBMU,PC
 SG_ D2M_DCDC_PCBTemp_17 : 24|8@1+ (1,-40) [-40|215] "℃"  MBMU,PC
 SG_ D2M_DCDC_MosTemp1_17 : 32|8@1+ (1,-40) [-40|215] "℃"  MBMU,PC
 SG_ D2M_DCDC_MosTemp2_17 : 40|8@1+ (1,-40) [-40|215] "℃"  MBMU,PC
 SG_ D2M_DCDC_TransformerTemp_17 : 48|8@1+ (1,-40) [-40|215] "℃"  MBMU,PC
 SG_ D2M_DCDC_Sleep_State_17 : 56|1@1+ (1,0) [0|1] ""  MBMU,PC
 SG_ D2M_SUMDATA1_Reserved_17 : 57|7@1+ (1,0) [0|127] ""  MBMU,PC

BO_ 2332884818 D2M_SUMDATA1__18: 8 DCDC
 SG_ D2M_SUMDATA1_CRC_18 : 0|8@1+ (1,0) [0|255] ""  MBMU,PC
 SG_ D2M_SUMDATA1_DCDC_Life_18 : 8|4@1+ (1,0) [0|15] ""  MBMU,PC
 SG_ D2M_DCDC_RQ_Mode_Set_18 : 12|2@1+ (1,0) [0|3] ""  MBMU,PC
 SG_ D2M_DCDC_Work_State_18 : 14|2@1+ (1,0) [0|3] ""  MBMU,PC
 SG_ D2M_DCDC_AlarmSigl_State_18 : 16|1@1+ (1,0) [0|1] ""  MBMU,PC
 SG_ D2M_DCDC_LVPower_State_18 : 17|1@1+ (1,0) [0|1] ""  MBMU,PC
 SG_ D2M_DCDC_Enableline_State_18 : 18|1@1+ (1,0) [0|1] ""  MBMU,PC
 SG_ D2M_Communication_State_18 : 19|1@1+ (1,0) [0|1] ""  MBMU,PC
 SG_ D2M_SUMDATA1_Reserved1_18 : 20|4@1+ (1,0) [0|15] ""  MBMU,PC
 SG_ D2M_DCDC_PCBTemp_18 : 24|8@1+ (1,-40) [-40|215] "℃"  MBMU,PC
 SG_ D2M_DCDC_MosTemp1_18 : 32|8@1+ (1,-40) [-40|215] "℃"  MBMU,PC
 SG_ D2M_DCDC_MosTemp2_18 : 40|8@1+ (1,-40) [-40|215] "℃"  MBMU,PC
 SG_ D2M_DCDC_TransformerTemp_18 : 48|8@1+ (1,-40) [-40|215] "℃"  MBMU,PC
 SG_ D2M_DCDC_Sleep_State_18 : 56|1@1+ (1,0) [0|1] ""  MBMU,PC
 SG_ D2M_SUMDATA1_Reserved_18 : 57|7@1+ (1,0) [0|127] ""  MBMU,PC

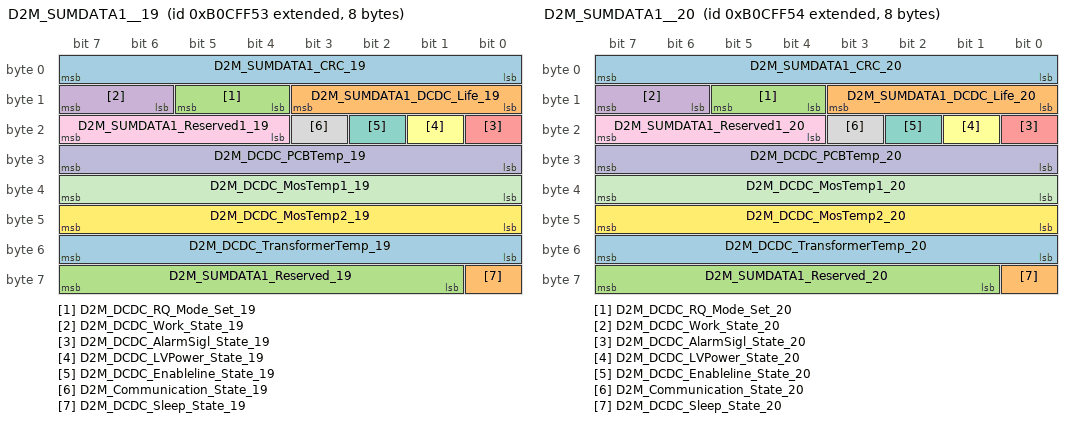
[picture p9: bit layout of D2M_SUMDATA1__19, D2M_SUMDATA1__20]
BO_ 2332884819 D2M_SUMDATA1__19: 8 DCDC
 SG_ D2M_SUMDATA1_CRC_19 : 0|8@1+ (1,0) [0|255] ""  MBMU,PC
 SG_ D2M_SUMDATA1_DCDC_Life_19 : 8|4@1+ (1,0) [0|15] ""  MBMU,PC
 SG_ D2M_DCDC_RQ_Mode_Set_19 : 12|2@1+ (1,0) [0|3] ""  MBMU,PC
 SG_ D2M_DCDC_Work_State_19 : 14|2@1+ (1,0) [0|3] ""  MBMU,PC
 SG_ D2M_DCDC_AlarmSigl_State_19 : 16|1@1+ (1,0) [0|1] ""  MBMU,PC
 SG_ D2M_DCDC_LVPower_State_19 : 17|1@1+ (1,0) [0|1] ""  MBMU,PC
 SG_ D2M_DCDC_Enableline_State_19 : 18|1@1+ (1,0) [0|1] ""  MBMU,PC
 SG_ D2M_Communication_State_19 : 19|1@1+ (1,0) [0|1] ""  MBMU,PC
 SG_ D2M_SUMDATA1_Reserved1_19 : 20|4@1+ (1,0) [0|15] ""  MBMU,PC
 SG_ D2M_DCDC_PCBTemp_19 : 24|8@1+ (1,-40) [-40|215] "℃"  MBMU,PC
 SG_ D2M_DCDC_MosTemp1_19 : 32|8@1+ (1,-40) [-40|215] "℃"  MBMU,PC
 SG_ D2M_DCDC_MosTemp2_19 : 40|8@1+ (1,-40) [-40|215] "℃"  MBMU,PC
 SG_ D2M_DCDC_TransformerTemp_19 : 48|8@1+ (1,-40) [-40|215] "℃"  MBMU,PC
 SG_ D2M_DCDC_Sleep_State_19 : 56|1@1+ (1,0) [0|1] ""  MBMU,PC
 SG_ D2M_SUMDATA1_Reserved_19 : 57|7@1+ (1,0) [0|127] ""  MBMU,PC

BO_ 2332884820 D2M_SUMDATA1__20: 8 DCDC
 SG_ D2M_SUMDATA1_CRC_20 : 0|8@1+ (1,0) [0|255] ""  MBMU,PC
 SG_ D2M_SUMDATA1_DCDC_Life_20 : 8|4@1+ (1,0) [0|15] ""  MBMU,PC
 SG_ D2M_DCDC_RQ_Mode_Set_20 : 12|2@1+ (1,0) [0|3] ""  MBMU,PC
 SG_ D2M_DCDC_Work_State_20 : 14|2@1+ (1,0) [0|3] ""  MBMU,PC
 SG_ D2M_DCDC_AlarmSigl_State_20 : 16|1@1+ (1,0) [0|1] ""  MBMU,PC
 SG_ D2M_DCDC_LVPower_State_20 : 17|1@1+ (1,0) [0|1] ""  MBMU,PC
 SG_ D2M_DCDC_Enableline_State_20 : 18|1@1+ (1,0) [0|1] ""  MBMU,PC
 SG_ D2M_Communication_State_20 : 19|1@1+ (1,0) [0|1] ""  MBMU,PC
 SG_ D2M_SUMDATA1_Reserved1_20 : 20|4@1+ (1,0) [0|15] ""  MBMU,PC
 SG_ D2M_DCDC_PCBTemp_20 : 24|8@1+ (1,-40) [-40|215] "℃"  MBMU,PC
 SG_ D2M_DCDC_MosTemp1_20 : 32|8@1+ (1,-40) [-40|215] "℃"  MBMU,PC
 SG_ D2M_DCDC_MosTemp2_20 : 40|8@1+ (1,-40) [-40|215] "℃"  MBMU,PC
 SG_ D2M_DCDC_TransformerTemp_20 : 48|8@1+ (1,-40) [-40|215] "℃"  MBMU,PC
 SG_ D2M_DCDC_Sleep_State_20 : 56|1@1+ (1,0) [0|1] ""  MBMU,PC
 SG_ D2M_SUMDATA1_Reserved_20 : 57|7@1+ (1,0) [0|127] ""  MBMU,PC

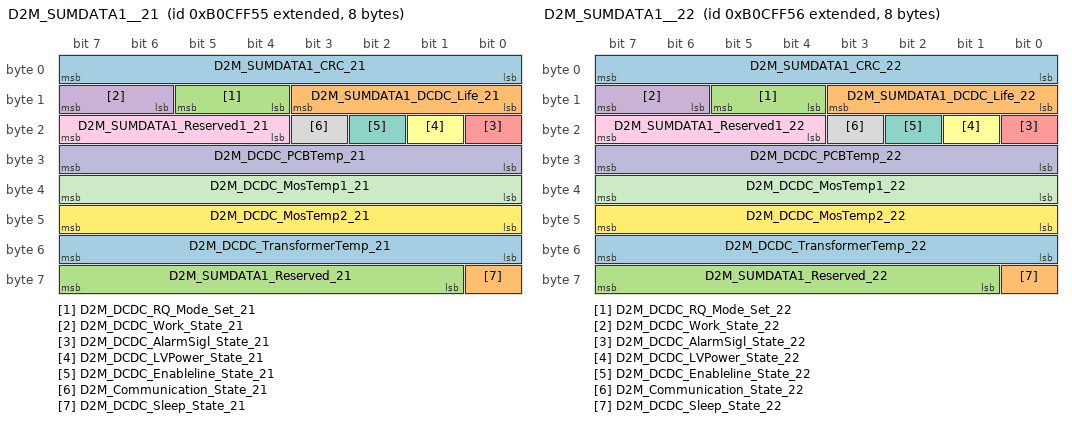
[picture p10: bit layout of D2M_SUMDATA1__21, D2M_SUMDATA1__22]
BO_ 2332884821 D2M_SUMDATA1__21: 8 DCDC
 SG_ D2M_SUMDATA1_CRC_21 : 0|8@1+ (1,0) [0|255] ""  MBMU,PC
 SG_ D2M_SUMDATA1_DCDC_Life_21 : 8|4@1+ (1,0) [0|15] ""  MBMU,PC
 SG_ D2M_DCDC_RQ_Mode_Set_21 : 12|2@1+ (1,0) [0|3] ""  MBMU,PC
 SG_ D2M_DCDC_Work_State_21 : 14|2@1+ (1,0) [0|3] ""  MBMU,PC
 SG_ D2M_DCDC_AlarmSigl_State_21 : 16|1@1+ (1,0) [0|1] ""  MBMU,PC
 SG_ D2M_DCDC_LVPower_State_21 : 17|1@1+ (1,0) [0|1] ""  MBMU,PC
 SG_ D2M_DCDC_Enableline_State_21 : 18|1@1+ (1,0) [0|1] ""  MBMU,PC
 SG_ D2M_Communication_State_21 : 19|1@1+ (1,0) [0|1] ""  MBMU,PC
 SG_ D2M_SUMDATA1_Reserved1_21 : 20|4@1+ (1,0) [0|15] ""  MBMU,PC
 SG_ D2M_DCDC_PCBTemp_21 : 24|8@1+ (1,-40) [-40|215] "℃"  MBMU,PC
 SG_ D2M_DCDC_MosTemp1_21 : 32|8@1+ (1,-40) [-40|215] "℃"  MBMU,PC
 SG_ D2M_DCDC_MosTemp2_21 : 40|8@1+ (1,-40) [-40|215] "℃"  MBMU,PC
 SG_ D2M_DCDC_TransformerTemp_21 : 48|8@1+ (1,-40) [-40|215] "℃"  MBMU,PC
 SG_ D2M_DCDC_Sleep_State_21 : 56|1@1+ (1,0) [0|1] ""  MBMU,PC
 SG_ D2M_SUMDATA1_Reserved_21 : 57|7@1+ (1,0) [0|127] ""  MBMU,PC

BO_ 2332884822 D2M_SUMDATA1__22: 8 DCDC
 SG_ D2M_SUMDATA1_CRC_22 : 0|8@1+ (1,0) [0|255] ""  MBMU,PC
 SG_ D2M_SUMDATA1_DCDC_Life_22 : 8|4@1+ (1,0) [0|15] ""  MBMU,PC
 SG_ D2M_DCDC_RQ_Mode_Set_22 : 12|2@1+ (1,0) [0|3] ""  MBMU,PC
 SG_ D2M_DCDC_Work_State_22 : 14|2@1+ (1,0) [0|3] ""  MBMU,PC
 SG_ D2M_DCDC_AlarmSigl_State_22 : 16|1@1+ (1,0) [0|1] ""  MBMU,PC
 SG_ D2M_DCDC_LVPower_State_22 : 17|1@1+ (1,0) [0|1] ""  MBMU,PC
 SG_ D2M_DCDC_Enableline_State_22 : 18|1@1+ (1,0) [0|1] ""  MBMU,PC
 SG_ D2M_Communication_State_22 : 19|1@1+ (1,0) [0|1] ""  MBMU,PC
 SG_ D2M_SUMDATA1_Reserved1_22 : 20|4@1+ (1,0) [0|15] ""  MBMU,PC
 SG_ D2M_DCDC_PCBTemp_22 : 24|8@1+ (1,-40) [-40|215] "℃"  MBMU,PC
 SG_ D2M_DCDC_MosTemp1_22 : 32|8@1+ (1,-40) [-40|215] "℃"  MBMU,PC
 SG_ D2M_DCDC_MosTemp2_22 : 40|8@1+ (1,-40) [-40|215] "℃"  MBMU,PC
 SG_ D2M_DCDC_TransformerTemp_22 : 48|8@1+ (1,-40) [-40|215] "℃"  MBMU,PC
 SG_ D2M_DCDC_Sleep_State_22 : 56|1@1+ (1,0) [0|1] ""  MBMU,PC
 SG_ D2M_SUMDATA1_Reserved_22 : 57|7@1+ (1,0) [0|127] ""  MBMU,PC

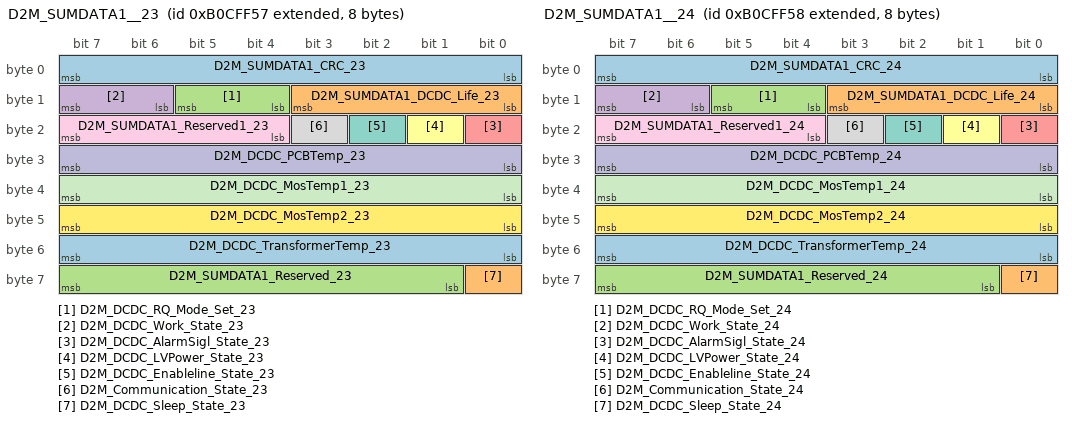
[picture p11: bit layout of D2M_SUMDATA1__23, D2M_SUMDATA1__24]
BO_ 2332884823 D2M_SUMDATA1__23: 8 DCDC
 SG_ D2M_SUMDATA1_CRC_23 : 0|8@1+ (1,0) [0|255] ""  MBMU,PC
 SG_ D2M_SUMDATA1_DCDC_Life_23 : 8|4@1+ (1,0) [0|15] ""  MBMU,PC
 SG_ D2M_DCDC_RQ_Mode_Set_23 : 12|2@1+ (1,0) [0|3] ""  MBMU,PC
 SG_ D2M_DCDC_Work_State_23 : 14|2@1+ (1,0) [0|3] ""  MBMU,PC
 SG_ D2M_DCDC_AlarmSigl_State_23 : 16|1@1+ (1,0) [0|1] ""  MBMU,PC
 SG_ D2M_DCDC_LVPower_State_23 : 17|1@1+ (1,0) [0|1] ""  MBMU,PC
 SG_ D2M_DCDC_Enableline_State_23 : 18|1@1+ (1,0) [0|1] ""  MBMU,PC
 SG_ D2M_Communication_State_23 : 19|1@1+ (1,0) [0|1] ""  MBMU,PC
 SG_ D2M_SUMDATA1_Reserved1_23 : 20|4@1+ (1,0) [0|15] ""  MBMU,PC
 SG_ D2M_DCDC_PCBTemp_23 : 24|8@1+ (1,-40) [-40|215] "℃"  MBMU,PC
 SG_ D2M_DCDC_MosTemp1_23 : 32|8@1+ (1,-40) [-40|215] "℃"  MBMU,PC
 SG_ D2M_DCDC_MosTemp2_23 : 40|8@1+ (1,-40) [-40|215] "℃"  MBMU,PC
 SG_ D2M_DCDC_TransformerTemp_23 : 48|8@1+ (1,-40) [-40|215] "℃"  MBMU,PC
 SG_ D2M_DCDC_Sleep_State_23 : 56|1@1+ (1,0) [0|1] ""  MBMU,PC
 SG_ D2M_SUMDATA1_Reserved_23 : 57|7@1+ (1,0) [0|127] ""  MBMU,PC

BO_ 2332884824 D2M_SUMDATA1__24: 8 DCDC
 SG_ D2M_SUMDATA1_CRC_24 : 0|8@1+ (1,0) [0|255] ""  MBMU,PC
 SG_ D2M_SUMDATA1_DCDC_Life_24 : 8|4@1+ (1,0) [0|15] ""  MBMU,PC
 SG_ D2M_DCDC_RQ_Mode_Set_24 : 12|2@1+ (1,0) [0|3] ""  MBMU,PC
 SG_ D2M_DCDC_Work_State_24 : 14|2@1+ (1,0) [0|3] ""  MBMU,PC
 SG_ D2M_DCDC_AlarmSigl_State_24 : 16|1@1+ (1,0) [0|1] ""  MBMU,PC
 SG_ D2M_DCDC_LVPower_State_24 : 17|1@1+ (1,0) [0|1] ""  MBMU,PC
 SG_ D2M_DCDC_Enableline_State_24 : 18|1@1+ (1,0) [0|1] ""  MBMU,PC
 SG_ D2M_Communication_State_24 : 19|1@1+ (1,0) [0|1] ""  MBMU,PC
 SG_ D2M_SUMDATA1_Reserved1_24 : 20|4@1+ (1,0) [0|15] ""  MBMU,PC
 SG_ D2M_DCDC_PCBTemp_24 : 24|8@1+ (1,-40) [-40|215] "℃"  MBMU,PC
 SG_ D2M_DCDC_MosTemp1_24 : 32|8@1+ (1,-40) [-40|215] "℃"  MBMU,PC
 SG_ D2M_DCDC_MosTemp2_24 : 40|8@1+ (1,-40) [-40|215] "℃"  MBMU,PC
 SG_ D2M_DCDC_TransformerTemp_24 : 48|8@1+ (1,-40) [-40|215] "℃"  MBMU,PC
 SG_ D2M_DCDC_Sleep_State_24 : 56|1@1+ (1,0) [0|1] ""  MBMU,PC
 SG_ D2M_SUMDATA1_Reserved_24 : 57|7@1+ (1,0) [0|127] ""  MBMU,PC

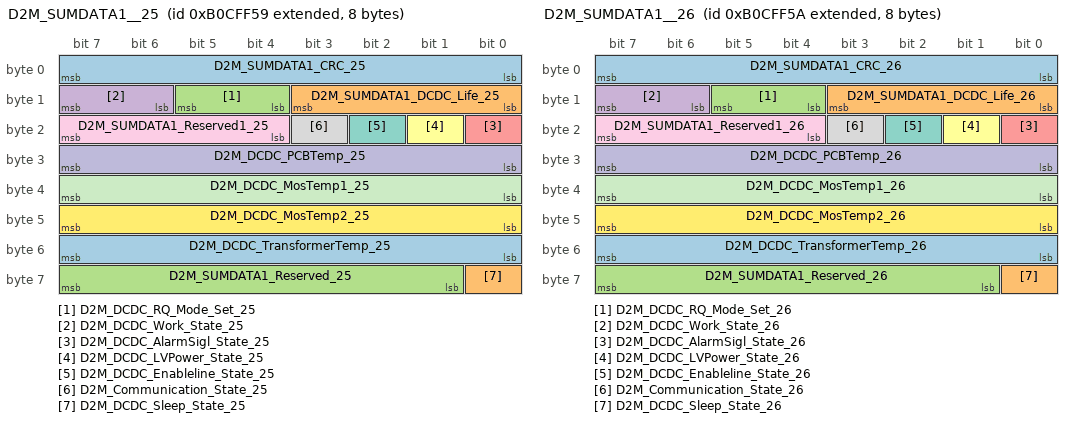
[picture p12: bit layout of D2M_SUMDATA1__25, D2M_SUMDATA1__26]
BO_ 2332884825 D2M_SUMDATA1__25: 8 DCDC
 SG_ D2M_SUMDATA1_CRC_25 : 0|8@1+ (1,0) [0|255] ""  MBMU,PC
 SG_ D2M_SUMDATA1_DCDC_Life_25 : 8|4@1+ (1,0) [0|15] ""  MBMU,PC
 SG_ D2M_DCDC_RQ_Mode_Set_25 : 12|2@1+ (1,0) [0|3] ""  MBMU,PC
 SG_ D2M_DCDC_Work_State_25 : 14|2@1+ (1,0) [0|3] ""  MBMU,PC
 SG_ D2M_DCDC_AlarmSigl_State_25 : 16|1@1+ (1,0) [0|1] ""  MBMU,PC
 SG_ D2M_DCDC_LVPower_State_25 : 17|1@1+ (1,0) [0|1] ""  MBMU,PC
 SG_ D2M_DCDC_Enableline_State_25 : 18|1@1+ (1,0) [0|1] ""  MBMU,PC
 SG_ D2M_Communication_State_25 : 19|1@1+ (1,0) [0|1] ""  MBMU,PC
 SG_ D2M_SUMDATA1_Reserved1_25 : 20|4@1+ (1,0) [0|15] ""  MBMU,PC
 SG_ D2M_DCDC_PCBTemp_25 : 24|8@1+ (1,-40) [-40|215] "℃"  MBMU,PC
 SG_ D2M_DCDC_MosTemp1_25 : 32|8@1+ (1,-40) [-40|215] "℃"  MBMU,PC
 SG_ D2M_DCDC_MosTemp2_25 : 40|8@1+ (1,-40) [-40|215] "℃"  MBMU,PC
 SG_ D2M_DCDC_TransformerTemp_25 : 48|8@1+ (1,-40) [-40|215] "℃"  MBMU,PC
 SG_ D2M_DCDC_Sleep_State_25 : 56|1@1+ (1,0) [0|1] ""  MBMU,PC
 SG_ D2M_SUMDATA1_Reserved_25 : 57|7@1+ (1,0) [0|127] ""  MBMU,PC

BO_ 2332884826 D2M_SUMDATA1__26: 8 DCDC
 SG_ D2M_SUMDATA1_CRC_26 : 0|8@1+ (1,0) [0|255] ""  MBMU,PC
 SG_ D2M_SUMDATA1_DCDC_Life_26 : 8|4@1+ (1,0) [0|15] ""  MBMU,PC
 SG_ D2M_DCDC_RQ_Mode_Set_26 : 12|2@1+ (1,0) [0|3] ""  MBMU,PC
 SG_ D2M_DCDC_Work_State_26 : 14|2@1+ (1,0) [0|3] ""  MBMU,PC
 SG_ D2M_DCDC_AlarmSigl_State_26 : 16|1@1+ (1,0) [0|1] ""  MBMU,PC
 SG_ D2M_DCDC_LVPower_State_26 : 17|1@1+ (1,0) [0|1] ""  MBMU,PC
 SG_ D2M_DCDC_Enableline_State_26 : 18|1@1+ (1,0) [0|1] ""  MBMU,PC
 SG_ D2M_Communication_State_26 : 19|1@1+ (1,0) [0|1] ""  MBMU,PC
 SG_ D2M_SUMDATA1_Reserved1_26 : 20|4@1+ (1,0) [0|15] ""  MBMU,PC
 SG_ D2M_DCDC_PCBTemp_26 : 24|8@1+ (1,-40) [-40|215] "℃"  MBMU,PC
 SG_ D2M_DCDC_MosTemp1_26 : 32|8@1+ (1,-40) [-40|215] "℃"  MBMU,PC
 SG_ D2M_DCDC_MosTemp2_26 : 40|8@1+ (1,-40) [-40|215] "℃"  MBMU,PC
 SG_ D2M_DCDC_TransformerTemp_26 : 48|8@1+ (1,-40) [-40|215] "℃"  MBMU,PC
 SG_ D2M_DCDC_Sleep_State_26 : 56|1@1+ (1,0) [0|1] ""  MBMU,PC
 SG_ D2M_SUMDATA1_Reserved_26 : 57|7@1+ (1,0) [0|127] ""  MBMU,PC

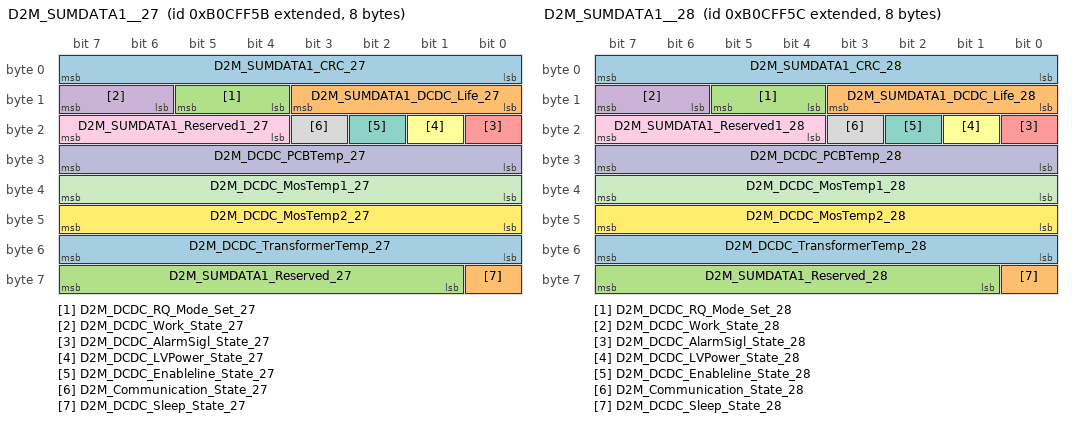
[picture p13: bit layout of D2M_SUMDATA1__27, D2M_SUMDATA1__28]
BO_ 2332884827 D2M_SUMDATA1__27: 8 DCDC
 SG_ D2M_SUMDATA1_CRC_27 : 0|8@1+ (1,0) [0|255] ""  MBMU,PC
 SG_ D2M_SUMDATA1_DCDC_Life_27 : 8|4@1+ (1,0) [0|15] ""  MBMU,PC
 SG_ D2M_DCDC_RQ_Mode_Set_27 : 12|2@1+ (1,0) [0|3] ""  MBMU,PC
 SG_ D2M_DCDC_Work_State_27 : 14|2@1+ (1,0) [0|3] ""  MBMU,PC
 SG_ D2M_DCDC_AlarmSigl_State_27 : 16|1@1+ (1,0) [0|1] ""  MBMU,PC
 SG_ D2M_DCDC_LVPower_State_27 : 17|1@1+ (1,0) [0|1] ""  MBMU,PC
 SG_ D2M_DCDC_Enableline_State_27 : 18|1@1+ (1,0) [0|1] ""  MBMU,PC
 SG_ D2M_Communication_State_27 : 19|1@1+ (1,0) [0|1] ""  MBMU,PC
 SG_ D2M_SUMDATA1_Reserved1_27 : 20|4@1+ (1,0) [0|15] ""  MBMU,PC
 SG_ D2M_DCDC_PCBTemp_27 : 24|8@1+ (1,-40) [-40|215] "℃"  MBMU,PC
 SG_ D2M_DCDC_MosTemp1_27 : 32|8@1+ (1,-40) [-40|215] "℃"  MBMU,PC
 SG_ D2M_DCDC_MosTemp2_27 : 40|8@1+ (1,-40) [-40|215] "℃"  MBMU,PC
 SG_ D2M_DCDC_TransformerTemp_27 : 48|8@1+ (1,-40) [-40|215] "℃"  MBMU,PC
 SG_ D2M_DCDC_Sleep_State_27 : 56|1@1+ (1,0) [0|1] ""  MBMU,PC
 SG_ D2M_SUMDATA1_Reserved_27 : 57|7@1+ (1,0) [0|127] ""  MBMU,PC

BO_ 2332884828 D2M_SUMDATA1__28: 8 DCDC
 SG_ D2M_SUMDATA1_CRC_28 : 0|8@1+ (1,0) [0|255] ""  MBMU,PC
 SG_ D2M_SUMDATA1_DCDC_Life_28 : 8|4@1+ (1,0) [0|15] ""  MBMU,PC
 SG_ D2M_DCDC_RQ_Mode_Set_28 : 12|2@1+ (1,0) [0|3] ""  MBMU,PC
 SG_ D2M_DCDC_Work_State_28 : 14|2@1+ (1,0) [0|3] ""  MBMU,PC
 SG_ D2M_DCDC_AlarmSigl_State_28 : 16|1@1+ (1,0) [0|1] ""  MBMU,PC
 SG_ D2M_DCDC_LVPower_State_28 : 17|1@1+ (1,0) [0|1] ""  MBMU,PC
 SG_ D2M_DCDC_Enableline_State_28 : 18|1@1+ (1,0) [0|1] ""  MBMU,PC
 SG_ D2M_Communication_State_28 : 19|1@1+ (1,0) [0|1] ""  MBMU,PC
 SG_ D2M_SUMDATA1_Reserved1_28 : 20|4@1+ (1,0) [0|15] ""  MBMU,PC
 SG_ D2M_DCDC_PCBTemp_28 : 24|8@1+ (1,-40) [-40|215] "℃"  MBMU,PC
 SG_ D2M_DCDC_MosTemp1_28 : 32|8@1+ (1,-40) [-40|215] "℃"  MBMU,PC
 SG_ D2M_DCDC_MosTemp2_28 : 40|8@1+ (1,-40) [-40|215] "℃"  MBMU,PC
 SG_ D2M_DCDC_TransformerTemp_28 : 48|8@1+ (1,-40) [-40|215] "℃"  MBMU,PC
 SG_ D2M_DCDC_Sleep_State_28 : 56|1@1+ (1,0) [0|1] ""  MBMU,PC
 SG_ D2M_SUMDATA1_Reserved_28 : 57|7@1+ (1,0) [0|127] ""  MBMU,PC

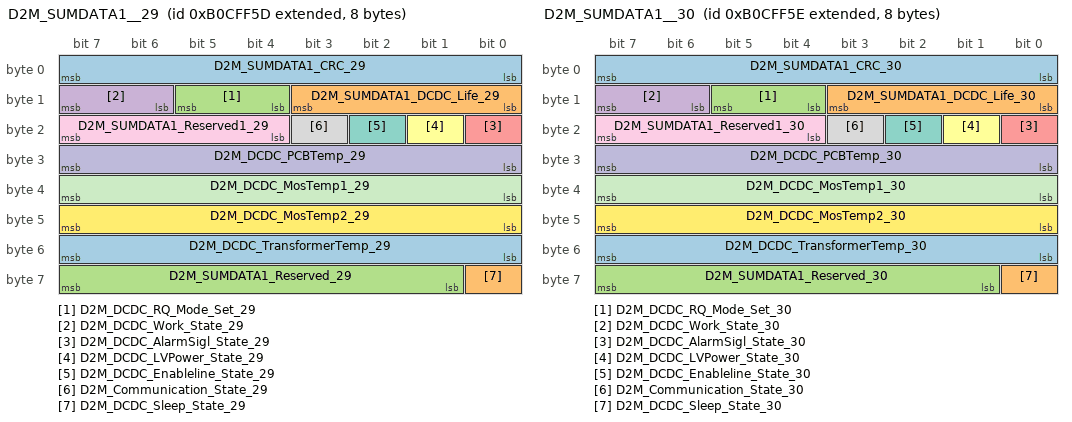
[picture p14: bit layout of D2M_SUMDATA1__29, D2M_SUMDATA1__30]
BO_ 2332884829 D2M_SUMDATA1__29: 8 DCDC
 SG_ D2M_SUMDATA1_CRC_29 : 0|8@1+ (1,0) [0|255] ""  MBMU,PC
 SG_ D2M_SUMDATA1_DCDC_Life_29 : 8|4@1+ (1,0) [0|15] ""  MBMU,PC
 SG_ D2M_DCDC_RQ_Mode_Set_29 : 12|2@1+ (1,0) [0|3] ""  MBMU,PC
 SG_ D2M_DCDC_Work_State_29 : 14|2@1+ (1,0) [0|3] ""  MBMU,PC
 SG_ D2M_DCDC_AlarmSigl_State_29 : 16|1@1+ (1,0) [0|1] ""  MBMU,PC
 SG_ D2M_DCDC_LVPower_State_29 : 17|1@1+ (1,0) [0|1] ""  MBMU,PC
 SG_ D2M_DCDC_Enableline_State_29 : 18|1@1+ (1,0) [0|1] ""  MBMU,PC
 SG_ D2M_Communication_State_29 : 19|1@1+ (1,0) [0|1] ""  MBMU,PC
 SG_ D2M_SUMDATA1_Reserved1_29 : 20|4@1+ (1,0) [0|15] ""  MBMU,PC
 SG_ D2M_DCDC_PCBTemp_29 : 24|8@1+ (1,-40) [-40|215] "℃"  MBMU,PC
 SG_ D2M_DCDC_MosTemp1_29 : 32|8@1+ (1,-40) [-40|215] "℃"  MBMU,PC
 SG_ D2M_DCDC_MosTemp2_29 : 40|8@1+ (1,-40) [-40|215] "℃"  MBMU,PC
 SG_ D2M_DCDC_TransformerTemp_29 : 48|8@1+ (1,-40) [-40|215] "℃"  MBMU,PC
 SG_ D2M_DCDC_Sleep_State_29 : 56|1@1+ (1,0) [0|1] ""  MBMU,PC
 SG_ D2M_SUMDATA1_Reserved_29 : 57|7@1+ (1,0) [0|127] ""  MBMU,PC

BO_ 2332884830 D2M_SUMDATA1__30: 8 DCDC
 SG_ D2M_SUMDATA1_CRC_30 : 0|8@1+ (1,0) [0|255] ""  MBMU,PC
 SG_ D2M_SUMDATA1_DCDC_Life_30 : 8|4@1+ (1,0) [0|15] ""  MBMU,PC
 SG_ D2M_DCDC_RQ_Mode_Set_30 : 12|2@1+ (1,0) [0|3] ""  MBMU,PC
 SG_ D2M_DCDC_Work_State_30 : 14|2@1+ (1,0) [0|3] ""  MBMU,PC
 SG_ D2M_DCDC_AlarmSigl_State_30 : 16|1@1+ (1,0) [0|1] ""  MBMU,PC
 SG_ D2M_DCDC_LVPower_State_30 : 17|1@1+ (1,0) [0|1] ""  MBMU,PC
 SG_ D2M_DCDC_Enableline_State_30 : 18|1@1+ (1,0) [0|1] ""  MBMU,PC
 SG_ D2M_Communication_State_30 : 19|1@1+ (1,0) [0|1] ""  MBMU,PC
 SG_ D2M_SUMDATA1_Reserved1_30 : 20|4@1+ (1,0) [0|15] ""  MBMU,PC
 SG_ D2M_DCDC_PCBTemp_30 : 24|8@1+ (1,-40) [-40|215] "℃"  MBMU,PC
 SG_ D2M_DCDC_MosTemp1_30 : 32|8@1+ (1,-40) [-40|215] "℃"  MBMU,PC
 SG_ D2M_DCDC_MosTemp2_30 : 40|8@1+ (1,-40) [-40|215] "℃"  MBMU,PC
 SG_ D2M_DCDC_TransformerTemp_30 : 48|8@1+ (1,-40) [-40|215] "℃"  MBMU,PC
 SG_ D2M_DCDC_Sleep_State_30 : 56|1@1+ (1,0) [0|1] ""  MBMU,PC
 SG_ D2M_SUMDATA1_Reserved_30 : 57|7@1+ (1,0) [0|127] ""  MBMU,PC

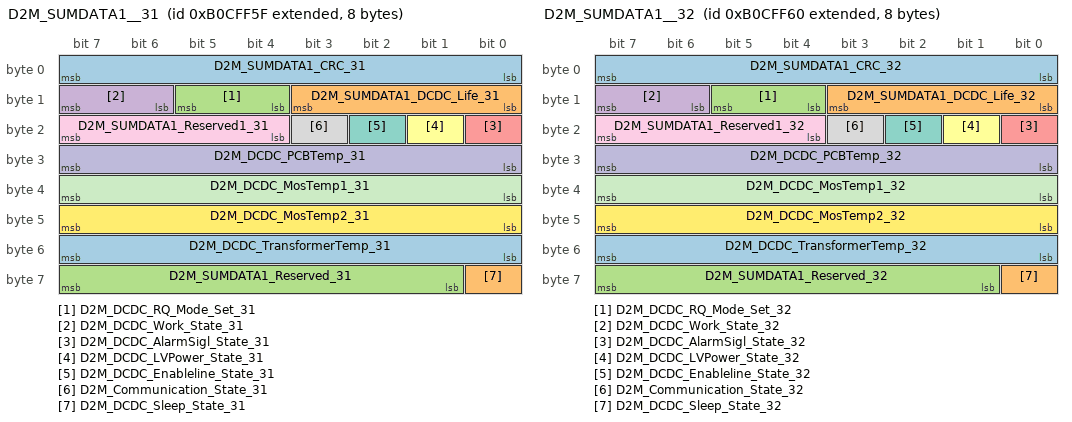
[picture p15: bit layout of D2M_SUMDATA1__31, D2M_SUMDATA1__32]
BO_ 2332884831 D2M_SUMDATA1__31: 8 DCDC
 SG_ D2M_SUMDATA1_CRC_31 : 0|8@1+ (1,0) [0|255] ""  MBMU,PC
 SG_ D2M_SUMDATA1_DCDC_Life_31 : 8|4@1+ (1,0) [0|15] ""  MBMU,PC
 SG_ D2M_DCDC_RQ_Mode_Set_31 : 12|2@1+ (1,0) [0|3] ""  MBMU,PC
 SG_ D2M_DCDC_Work_State_31 : 14|2@1+ (1,0) [0|3] ""  MBMU,PC
 SG_ D2M_DCDC_AlarmSigl_State_31 : 16|1@1+ (1,0) [0|1] ""  MBMU,PC
 SG_ D2M_DCDC_LVPower_State_31 : 17|1@1+ (1,0) [0|1] ""  MBMU,PC
 SG_ D2M_DCDC_Enableline_State_31 : 18|1@1+ (1,0) [0|1] ""  MBMU,PC
 SG_ D2M_Communication_State_31 : 19|1@1+ (1,0) [0|1] ""  MBMU,PC
 SG_ D2M_SUMDATA1_Reserved1_31 : 20|4@1+ (1,0) [0|15] ""  MBMU,PC
 SG_ D2M_DCDC_PCBTemp_31 : 24|8@1+ (1,-40) [-40|215] "℃"  MBMU,PC
 SG_ D2M_DCDC_MosTemp1_31 : 32|8@1+ (1,-40) [-40|215] "℃"  MBMU,PC
 SG_ D2M_DCDC_MosTemp2_31 : 40|8@1+ (1,-40) [-40|215] "℃"  MBMU,PC
 SG_ D2M_DCDC_TransformerTemp_31 : 48|8@1+ (1,-40) [-40|215] "℃"  MBMU,PC
 SG_ D2M_DCDC_Sleep_State_31 : 56|1@1+ (1,0) [0|1] ""  MBMU,PC
 SG_ D2M_SUMDATA1_Reserved_31 : 57|7@1+ (1,0) [0|127] ""  MBMU,PC

BO_ 2332884832 D2M_SUMDATA1__32: 8 DCDC
 SG_ D2M_SUMDATA1_CRC_32 : 0|8@1+ (1,0) [0|255] ""  MBMU,PC
 SG_ D2M_SUMDATA1_DCDC_Life_32 : 8|4@1+ (1,0) [0|15] ""  MBMU,PC
 SG_ D2M_DCDC_RQ_Mode_Set_32 : 12|2@1+ (1,0) [0|3] ""  MBMU,PC
 SG_ D2M_DCDC_Work_State_32 : 14|2@1+ (1,0) [0|3] ""  MBMU,PC
 SG_ D2M_DCDC_AlarmSigl_State_32 : 16|1@1+ (1,0) [0|1] ""  MBMU,PC
 SG_ D2M_DCDC_LVPower_State_32 : 17|1@1+ (1,0) [0|1] ""  MBMU,PC
 SG_ D2M_DCDC_Enableline_State_32 : 18|1@1+ (1,0) [0|1] ""  MBMU,PC
 SG_ D2M_Communication_State_32 : 19|1@1+ (1,0) [0|1] ""  MBMU,PC
 SG_ D2M_SUMDATA1_Reserved1_32 : 20|4@1+ (1,0) [0|15] ""  MBMU,PC
 SG_ D2M_DCDC_PCBTemp_32 : 24|8@1+ (1,-40) [-40|215] "℃"  MBMU,PC
 SG_ D2M_DCDC_MosTemp1_32 : 32|8@1+ (1,-40) [-40|215] "℃"  MBMU,PC
 SG_ D2M_DCDC_MosTemp2_32 : 40|8@1+ (1,-40) [-40|215] "℃"  MBMU,PC
 SG_ D2M_DCDC_TransformerTemp_32 : 48|8@1+ (1,-40) [-40|215] "℃"  MBMU,PC
 SG_ D2M_DCDC_Sleep_State_32 : 56|1@1+ (1,0) [0|1] ""  MBMU,PC
 SG_ D2M_SUMDATA1_Reserved_32 : 57|7@1+ (1,0) [0|127] ""  MBMU,PC

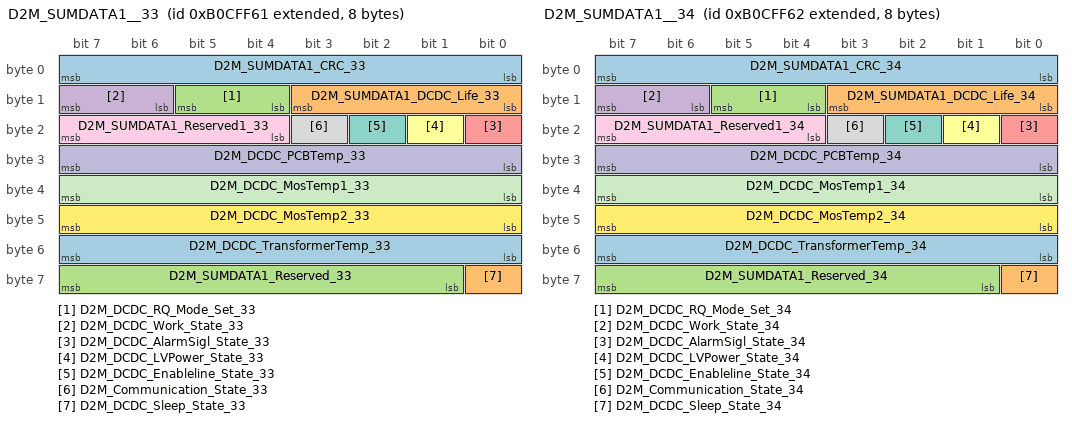
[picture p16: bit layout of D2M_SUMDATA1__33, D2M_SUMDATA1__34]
BO_ 2332884833 D2M_SUMDATA1__33: 8 DCDC
 SG_ D2M_SUMDATA1_CRC_33 : 0|8@1+ (1,0) [0|255] ""  MBMU,PC
 SG_ D2M_SUMDATA1_DCDC_Life_33 : 8|4@1+ (1,0) [0|15] ""  MBMU,PC
 SG_ D2M_DCDC_RQ_Mode_Set_33 : 12|2@1+ (1,0) [0|3] ""  MBMU,PC
 SG_ D2M_DCDC_Work_State_33 : 14|2@1+ (1,0) [0|3] ""  MBMU,PC
 SG_ D2M_DCDC_AlarmSigl_State_33 : 16|1@1+ (1,0) [0|1] ""  MBMU,PC
 SG_ D2M_DCDC_LVPower_State_33 : 17|1@1+ (1,0) [0|1] ""  MBMU,PC
 SG_ D2M_DCDC_Enableline_State_33 : 18|1@1+ (1,0) [0|1] ""  MBMU,PC
 SG_ D2M_Communication_State_33 : 19|1@1+ (1,0) [0|1] ""  MBMU,PC
 SG_ D2M_SUMDATA1_Reserved1_33 : 20|4@1+ (1,0) [0|15] ""  MBMU,PC
 SG_ D2M_DCDC_PCBTemp_33 : 24|8@1+ (1,-40) [-40|215] "℃"  MBMU,PC
 SG_ D2M_DCDC_MosTemp1_33 : 32|8@1+ (1,-40) [-40|215] "℃"  MBMU,PC
 SG_ D2M_DCDC_MosTemp2_33 : 40|8@1+ (1,-40) [-40|215] "℃"  MBMU,PC
 SG_ D2M_DCDC_TransformerTemp_33 : 48|8@1+ (1,-40) [-40|215] "℃"  MBMU,PC
 SG_ D2M_DCDC_Sleep_State_33 : 56|1@1+ (1,0) [0|1] ""  MBMU,PC
 SG_ D2M_SUMDATA1_Reserved_33 : 57|7@1+ (1,0) [0|127] ""  MBMU,PC

BO_ 2332884834 D2M_SUMDATA1__34: 8 DCDC
 SG_ D2M_SUMDATA1_CRC_34 : 0|8@1+ (1,0) [0|255] ""  MBMU,PC
 SG_ D2M_SUMDATA1_DCDC_Life_34 : 8|4@1+ (1,0) [0|15] ""  MBMU,PC
 SG_ D2M_DCDC_RQ_Mode_Set_34 : 12|2@1+ (1,0) [0|3] ""  MBMU,PC
 SG_ D2M_DCDC_Work_State_34 : 14|2@1+ (1,0) [0|3] ""  MBMU,PC
 SG_ D2M_DCDC_AlarmSigl_State_34 : 16|1@1+ (1,0) [0|1] ""  MBMU,PC
 SG_ D2M_DCDC_LVPower_State_34 : 17|1@1+ (1,0) [0|1] ""  MBMU,PC
 SG_ D2M_DCDC_Enableline_State_34 : 18|1@1+ (1,0) [0|1] ""  MBMU,PC
 SG_ D2M_Communication_State_34 : 19|1@1+ (1,0) [0|1] ""  MBMU,PC
 SG_ D2M_SUMDATA1_Reserved1_34 : 20|4@1+ (1,0) [0|15] ""  MBMU,PC
 SG_ D2M_DCDC_PCBTemp_34 : 24|8@1+ (1,-40) [-40|215] "℃"  MBMU,PC
 SG_ D2M_DCDC_MosTemp1_34 : 32|8@1+ (1,-40) [-40|215] "℃"  MBMU,PC
 SG_ D2M_DCDC_MosTemp2_34 : 40|8@1+ (1,-40) [-40|215] "℃"  MBMU,PC
 SG_ D2M_DCDC_TransformerTemp_34 : 48|8@1+ (1,-40) [-40|215] "℃"  MBMU,PC
 SG_ D2M_DCDC_Sleep_State_34 : 56|1@1+ (1,0) [0|1] ""  MBMU,PC
 SG_ D2M_SUMDATA1_Reserved_34 : 57|7@1+ (1,0) [0|127] ""  MBMU,PC

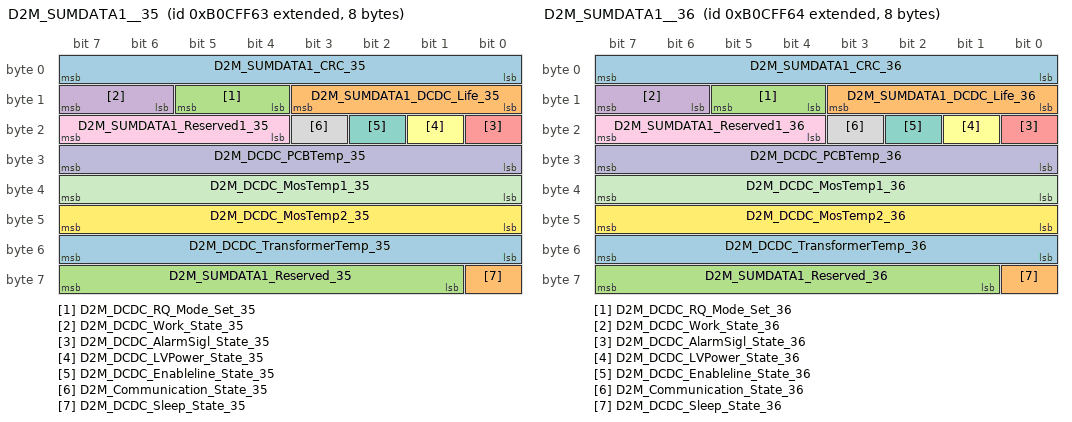
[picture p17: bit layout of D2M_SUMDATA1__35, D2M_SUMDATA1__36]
BO_ 2332884835 D2M_SUMDATA1__35: 8 DCDC
 SG_ D2M_SUMDATA1_CRC_35 : 0|8@1+ (1,0) [0|255] ""  MBMU,PC
 SG_ D2M_SUMDATA1_DCDC_Life_35 : 8|4@1+ (1,0) [0|15] ""  MBMU,PC
 SG_ D2M_DCDC_RQ_Mode_Set_35 : 12|2@1+ (1,0) [0|3] ""  MBMU,PC
 SG_ D2M_DCDC_Work_State_35 : 14|2@1+ (1,0) [0|3] ""  MBMU,PC
 SG_ D2M_DCDC_AlarmSigl_State_35 : 16|1@1+ (1,0) [0|1] ""  MBMU,PC
 SG_ D2M_DCDC_LVPower_State_35 : 17|1@1+ (1,0) [0|1] ""  MBMU,PC
 SG_ D2M_DCDC_Enableline_State_35 : 18|1@1+ (1,0) [0|1] ""  MBMU,PC
 SG_ D2M_Communication_State_35 : 19|1@1+ (1,0) [0|1] ""  MBMU,PC
 SG_ D2M_SUMDATA1_Reserved1_35 : 20|4@1+ (1,0) [0|15] ""  MBMU,PC
 SG_ D2M_DCDC_PCBTemp_35 : 24|8@1+ (1,-40) [-40|215] "℃"  MBMU,PC
 SG_ D2M_DCDC_MosTemp1_35 : 32|8@1+ (1,-40) [-40|215] "℃"  MBMU,PC
 SG_ D2M_DCDC_MosTemp2_35 : 40|8@1+ (1,-40) [-40|215] "℃"  MBMU,PC
 SG_ D2M_DCDC_TransformerTemp_35 : 48|8@1+ (1,-40) [-40|215] "℃"  MBMU,PC
 SG_ D2M_DCDC_Sleep_State_35 : 56|1@1+ (1,0) [0|1] ""  MBMU,PC
 SG_ D2M_SUMDATA1_Reserved_35 : 57|7@1+ (1,0) [0|127] ""  MBMU,PC

BO_ 2332884836 D2M_SUMDATA1__36: 8 DCDC
 SG_ D2M_SUMDATA1_CRC_36 : 0|8@1+ (1,0) [0|255] ""  MBMU,PC
 SG_ D2M_SUMDATA1_DCDC_Life_36 : 8|4@1+ (1,0) [0|15] ""  MBMU,PC
 SG_ D2M_DCDC_RQ_Mode_Set_36 : 12|2@1+ (1,0) [0|3] ""  MBMU,PC
 SG_ D2M_DCDC_Work_State_36 : 14|2@1+ (1,0) [0|3] ""  MBMU,PC
 SG_ D2M_DCDC_AlarmSigl_State_36 : 16|1@1+ (1,0) [0|1] ""  MBMU,PC
 SG_ D2M_DCDC_LVPower_State_36 : 17|1@1+ (1,0) [0|1] ""  MBMU,PC
 SG_ D2M_DCDC_Enableline_State_36 : 18|1@1+ (1,0) [0|1] ""  MBMU,PC
 SG_ D2M_Communication_State_36 : 19|1@1+ (1,0) [0|1] ""  MBMU,PC
 SG_ D2M_SUMDATA1_Reserved1_36 : 20|4@1+ (1,0) [0|15] ""  MBMU,PC
 SG_ D2M_DCDC_PCBTemp_36 : 24|8@1+ (1,-40) [-40|215] "℃"  MBMU,PC
 SG_ D2M_DCDC_MosTemp1_36 : 32|8@1+ (1,-40) [-40|215] "℃"  MBMU,PC
 SG_ D2M_DCDC_MosTemp2_36 : 40|8@1+ (1,-40) [-40|215] "℃"  MBMU,PC
 SG_ D2M_DCDC_TransformerTemp_36 : 48|8@1+ (1,-40) [-40|215] "℃"  MBMU,PC
 SG_ D2M_DCDC_Sleep_State_36 : 56|1@1+ (1,0) [0|1] ""  MBMU,PC
 SG_ D2M_SUMDATA1_Reserved_36 : 57|7@1+ (1,0) [0|127] ""  MBMU,PC

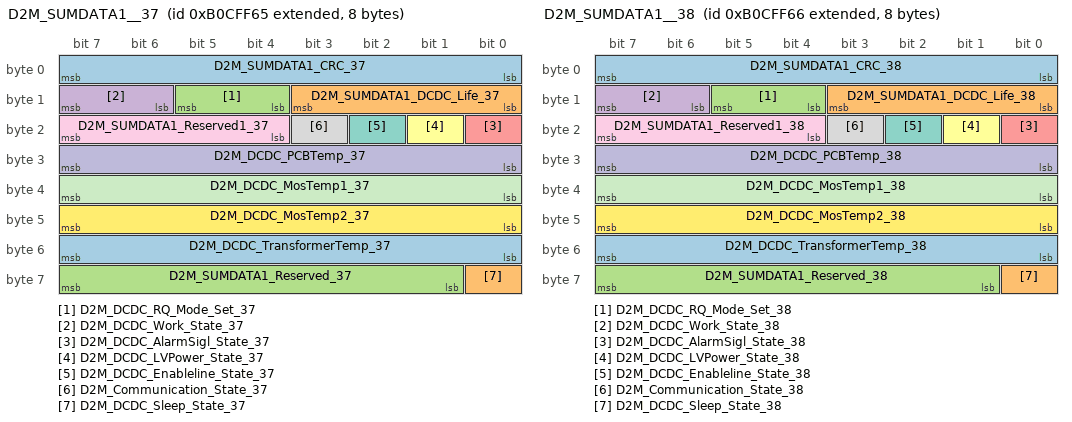
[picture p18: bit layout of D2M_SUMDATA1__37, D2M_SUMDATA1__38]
BO_ 2332884837 D2M_SUMDATA1__37: 8 DCDC
 SG_ D2M_SUMDATA1_CRC_37 : 0|8@1+ (1,0) [0|255] ""  MBMU,PC
 SG_ D2M_SUMDATA1_DCDC_Life_37 : 8|4@1+ (1,0) [0|15] ""  MBMU,PC
 SG_ D2M_DCDC_RQ_Mode_Set_37 : 12|2@1+ (1,0) [0|3] ""  MBMU,PC
 SG_ D2M_DCDC_Work_State_37 : 14|2@1+ (1,0) [0|3] ""  MBMU,PC
 SG_ D2M_DCDC_AlarmSigl_State_37 : 16|1@1+ (1,0) [0|1] ""  MBMU,PC
 SG_ D2M_DCDC_LVPower_State_37 : 17|1@1+ (1,0) [0|1] ""  MBMU,PC
 SG_ D2M_DCDC_Enableline_State_37 : 18|1@1+ (1,0) [0|1] ""  MBMU,PC
 SG_ D2M_Communication_State_37 : 19|1@1+ (1,0) [0|1] ""  MBMU,PC
 SG_ D2M_SUMDATA1_Reserved1_37 : 20|4@1+ (1,0) [0|15] ""  MBMU,PC
 SG_ D2M_DCDC_PCBTemp_37 : 24|8@1+ (1,-40) [-40|215] "℃"  MBMU,PC
 SG_ D2M_DCDC_MosTemp1_37 : 32|8@1+ (1,-40) [-40|215] "℃"  MBMU,PC
 SG_ D2M_DCDC_MosTemp2_37 : 40|8@1+ (1,-40) [-40|215] "℃"  MBMU,PC
 SG_ D2M_DCDC_TransformerTemp_37 : 48|8@1+ (1,-40) [-40|215] "℃"  MBMU,PC
 SG_ D2M_DCDC_Sleep_State_37 : 56|1@1+ (1,0) [0|1] ""  MBMU,PC
 SG_ D2M_SUMDATA1_Reserved_37 : 57|7@1+ (1,0) [0|127] ""  MBMU,PC

BO_ 2332884838 D2M_SUMDATA1__38: 8 DCDC
 SG_ D2M_SUMDATA1_CRC_38 : 0|8@1+ (1,0) [0|255] ""  MBMU,PC
 SG_ D2M_SUMDATA1_DCDC_Life_38 : 8|4@1+ (1,0) [0|15] ""  MBMU,PC
 SG_ D2M_DCDC_RQ_Mode_Set_38 : 12|2@1+ (1,0) [0|3] ""  MBMU,PC
 SG_ D2M_DCDC_Work_State_38 : 14|2@1+ (1,0) [0|3] ""  MBMU,PC
 SG_ D2M_DCDC_AlarmSigl_State_38 : 16|1@1+ (1,0) [0|1] ""  MBMU,PC
 SG_ D2M_DCDC_LVPower_State_38 : 17|1@1+ (1,0) [0|1] ""  MBMU,PC
 SG_ D2M_DCDC_Enableline_State_38 : 18|1@1+ (1,0) [0|1] ""  MBMU,PC
 SG_ D2M_Communication_State_38 : 19|1@1+ (1,0) [0|1] ""  MBMU,PC
 SG_ D2M_SUMDATA1_Reserved1_38 : 20|4@1+ (1,0) [0|15] ""  MBMU,PC
 SG_ D2M_DCDC_PCBTemp_38 : 24|8@1+ (1,-40) [-40|215] "℃"  MBMU,PC
 SG_ D2M_DCDC_MosTemp1_38 : 32|8@1+ (1,-40) [-40|215] "℃"  MBMU,PC
 SG_ D2M_DCDC_MosTemp2_38 : 40|8@1+ (1,-40) [-40|215] "℃"  MBMU,PC
 SG_ D2M_DCDC_TransformerTemp_38 : 48|8@1+ (1,-40) [-40|215] "℃"  MBMU,PC
 SG_ D2M_DCDC_Sleep_State_38 : 56|1@1+ (1,0) [0|1] ""  MBMU,PC
 SG_ D2M_SUMDATA1_Reserved_38 : 57|7@1+ (1,0) [0|127] ""  MBMU,PC

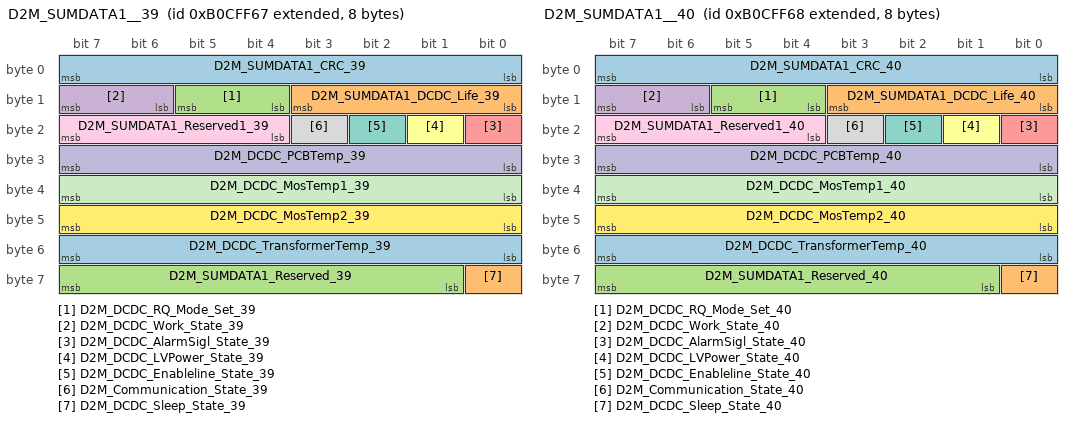
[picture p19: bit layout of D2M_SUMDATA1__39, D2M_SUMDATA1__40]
BO_ 2332884839 D2M_SUMDATA1__39: 8 DCDC
 SG_ D2M_SUMDATA1_CRC_39 : 0|8@1+ (1,0) [0|255] ""  MBMU,PC
 SG_ D2M_SUMDATA1_DCDC_Life_39 : 8|4@1+ (1,0) [0|15] ""  MBMU,PC
 SG_ D2M_DCDC_RQ_Mode_Set_39 : 12|2@1+ (1,0) [0|3] ""  MBMU,PC
 SG_ D2M_DCDC_Work_State_39 : 14|2@1+ (1,0) [0|3] ""  MBMU,PC
 SG_ D2M_DCDC_AlarmSigl_State_39 : 16|1@1+ (1,0) [0|1] ""  MBMU,PC
 SG_ D2M_DCDC_LVPower_State_39 : 17|1@1+ (1,0) [0|1] ""  MBMU,PC
 SG_ D2M_DCDC_Enableline_State_39 : 18|1@1+ (1,0) [0|1] ""  MBMU,PC
 SG_ D2M_Communication_State_39 : 19|1@1+ (1,0) [0|1] ""  MBMU,PC
 SG_ D2M_SUMDATA1_Reserved1_39 : 20|4@1+ (1,0) [0|15] ""  MBMU,PC
 SG_ D2M_DCDC_PCBTemp_39 : 24|8@1+ (1,-40) [-40|215] "℃"  MBMU,PC
 SG_ D2M_DCDC_MosTemp1_39 : 32|8@1+ (1,-40) [-40|215] "℃"  MBMU,PC
 SG_ D2M_DCDC_MosTemp2_39 : 40|8@1+ (1,-40) [-40|215] "℃"  MBMU,PC
 SG_ D2M_DCDC_TransformerTemp_39 : 48|8@1+ (1,-40) [-40|215] "℃"  MBMU,PC
 SG_ D2M_DCDC_Sleep_State_39 : 56|1@1+ (1,0) [0|1] ""  MBMU,PC
 SG_ D2M_SUMDATA1_Reserved_39 : 57|7@1+ (1,0) [0|127] ""  MBMU,PC

BO_ 2332884840 D2M_SUMDATA1__40: 8 DCDC
 SG_ D2M_SUMDATA1_CRC_40 : 0|8@1+ (1,0) [0|255] ""  MBMU,PC
 SG_ D2M_SUMDATA1_DCDC_Life_40 : 8|4@1+ (1,0) [0|15] ""  MBMU,PC
 SG_ D2M_DCDC_RQ_Mode_Set_40 : 12|2@1+ (1,0) [0|3] ""  MBMU,PC
 SG_ D2M_DCDC_Work_State_40 : 14|2@1+ (1,0) [0|3] ""  MBMU,PC
 SG_ D2M_DCDC_AlarmSigl_State_40 : 16|1@1+ (1,0) [0|1] ""  MBMU,PC
 SG_ D2M_DCDC_LVPower_State_40 : 17|1@1+ (1,0) [0|1] ""  MBMU,PC
 SG_ D2M_DCDC_Enableline_State_40 : 18|1@1+ (1,0) [0|1] ""  MBMU,PC
 SG_ D2M_Communication_State_40 : 19|1@1+ (1,0) [0|1] ""  MBMU,PC
 SG_ D2M_SUMDATA1_Reserved1_40 : 20|4@1+ (1,0) [0|15] ""  MBMU,PC
 SG_ D2M_DCDC_PCBTemp_40 : 24|8@1+ (1,-40) [-40|215] "℃"  MBMU,PC
 SG_ D2M_DCDC_MosTemp1_40 : 32|8@1+ (1,-40) [-40|215] "℃"  MBMU,PC
 SG_ D2M_DCDC_MosTemp2_40 : 40|8@1+ (1,-40) [-40|215] "℃"  MBMU,PC
 SG_ D2M_DCDC_TransformerTemp_40 : 48|8@1+ (1,-40) [-40|215] "℃"  MBMU,PC
 SG_ D2M_DCDC_Sleep_State_40 : 56|1@1+ (1,0) [0|1] ""  MBMU,PC
 SG_ D2M_SUMDATA1_Reserved_40 : 57|7@1+ (1,0) [0|127] ""  MBMU,PC

BO_ 2332884841 D2M_SUMDATA1__41: 8 DCDC
 SG_ D2M_SUMDATA1_CRC_41 : 0|8@1+ (1,0) [0|255] ""  MBMU,PC
 SG_ D2M_SUMDATA1_DCDC_Life_41 : 8|4@1+ (1,0) [0|15] ""  MBMU,PC
 SG_ D2M_DCDC_RQ_Mode_Set_41 : 12|2@1+ (1,0) [0|3] ""  MBMU,PC
 SG_ D2M_DCDC_Work_State_41 : 14|2@1+ (1,0) [0|3] ""  MBMU,PC
 SG_ D2M_DCDC_AlarmSigl_State_41 : 16|1@1+ (1,0) [0|1] ""  MBMU,PC
 SG_ D2M_DCDC_LVPower_State_41 : 17|1@1+ (1,0) [0|1] ""  MBMU,PC
 SG_ D2M_DCDC_Enableline_State_41 : 18|1@1+ (1,0) [0|1] ""  MBMU,PC
 SG_ D2M_Communication_State_41 : 19|1@1+ (1,0) [0|1] ""  MBMU,PC
 SG_ D2M_SUMDATA1_Reserved1_41 : 20|4@1+ (1,0) [0|15] ""  MBMU,PC
 SG_ D2M_DCDC_PCBTemp_41 : 24|8@1+ (1,-40) [-40|215] "℃"  MBMU,PC
 SG_ D2M_DCDC_MosTemp1_41 : 32|8@1+ (1,-40) [-40|215] "℃"  MBMU,PC
 SG_ D2M_DCDC_MosTemp2_41 : 40|8@1+ (1,-40) [-40|215] "℃"  MBMU,PC
 SG_ D2M_DCDC_TransformerTemp_41 : 48|8@1+ (1,-40) [-40|215] "℃"  MBMU,PC
 SG_ D2M_DCDC_Sleep_State_41 : 56|1@1+ (1,0) [0|1] ""  MBMU,PC
 SG_ D2M_SUMDATA1_Reserved_41 : 57|7@1+ (1,0) [0|127] ""  MBMU,PC

BO_ 2332884842 D2M_SUMDATA1__42: 8 DCDC
 SG_ D2M_SUMDATA1_CRC_42 : 0|8@1+ (1,0) [0|255] ""  MBMU,PC
 SG_ D2M_SUMDATA1_DCDC_Life_42 : 8|4@1+ (1,0) [0|15] ""  MBMU,PC
 SG_ D2M_DCDC_RQ_Mode_Set_42 : 12|2@1+ (1,0) [0|3] ""  MBMU,PC
 SG_ D2M_DCDC_Work_State_42 : 14|2@1+ (1,0) [0|3] ""  MBMU,PC
 SG_ D2M_DCDC_AlarmSigl_State_42 : 16|1@1+ (1,0) [0|1] ""  MBMU,PC
 SG_ D2M_DCDC_LVPower_State_42 : 17|1@1+ (1,0) [0|1] ""  MBMU,PC
 SG_ D2M_DCDC_Enableline_State_42 : 18|1@1+ (1,0) [0|1] ""  MBMU,PC
 SG_ D2M_Communication_State_42 : 19|1@1+ (1,0) [0|1] ""  MBMU,PC
 SG_ D2M_SUMDATA1_Reserved1_42 : 20|4@1+ (1,0) [0|15] ""  MBMU,PC
 SG_ D2M_DCDC_PCBTemp_42 : 24|8@1+ (1,-40) [-40|215] "℃"  MBMU,PC
 SG_ D2M_DCDC_MosTemp1_42 : 32|8@1+ (1,-40) [-40|215] "℃"  MBMU,PC
 SG_ D2M_DCDC_MosTemp2_42 : 40|8@1+ (1,-40) [-40|215] "℃"  MBMU,PC
 SG_ D2M_DCDC_TransformerTemp_42 : 48|8@1+ (1,-40) [-40|215] "℃"  MBMU,PC
 SG_ D2M_DCDC_Sleep_State_42 : 56|1@1+ (1,0) [0|1] ""  MBMU,PC
 SG_ D2M_SUMDATA1_Reserved_42 : 57|7@1+ (1,0) [0|127] ""  MBMU,PC

BO_ 2332884843 D2M_SUMDATA1__43: 8 DCDC
 SG_ D2M_SUMDATA1_CRC_43 : 0|8@1+ (1,0) [0|255] ""  MBMU,PC
 SG_ D2M_SUMDATA1_DCDC_Life_43 : 8|4@1+ (1,0) [0|15] ""  MBMU,PC
 SG_ D2M_DCDC_RQ_Mode_Set_43 : 12|2@1+ (1,0) [0|3] ""  MBMU,PC
 SG_ D2M_DCDC_Work_State_43 : 14|2@1+ (1,0) [0|3] ""  MBMU,PC
 SG_ D2M_DCDC_AlarmSigl_State_43 : 16|1@1+ (1,0) [0|1] ""  MBMU,PC
 SG_ D2M_DCDC_LVPower_State_43 : 17|1@1+ (1,0) [0|1] ""  MBMU,PC
 SG_ D2M_DCDC_Enableline_State_43 : 18|1@1+ (1,0) [0|1] ""  MBMU,PC
 SG_ D2M_Communication_State_43 : 19|1@1+ (1,0) [0|1] ""  MBMU,PC
 SG_ D2M_SUMDATA1_Reserved1_43 : 20|4@1+ (1,0) [0|15] ""  MBMU,PC
 SG_ D2M_DCDC_PCBTemp_43 : 24|8@1+ (1,-40) [-40|215] "℃"  MBMU,PC
 SG_ D2M_DCDC_MosTemp1_43 : 32|8@1+ (1,-40) [-40|215] "℃"  MBMU,PC
 SG_ D2M_DCDC_MosTemp2_43 : 40|8@1+ (1,-40) [-40|215] "℃"  MBMU,PC
 SG_ D2M_DCDC_TransformerTemp_43 : 48|8@1+ (1,-40) [-40|215] "℃"  MBMU,PC
 SG_ D2M_DCDC_Sleep_State_43 : 56|1@1+ (1,0) [0|1] ""  MBMU,PC
 SG_ D2M_SUMDATA1_Reserved_43 : 57|7@1+ (1,0) [0|127] ""  MBMU,PC

BO_ 2332884844 D2M_SUMDATA1__44: 8 DCDC
 SG_ D2M_SUMDATA1_CRC_44 : 0|8@1+ (1,0) [0|255] ""  MBMU,PC
 SG_ D2M_SUMDATA1_DCDC_Life_44 : 8|4@1+ (1,0) [0|15] ""  MBMU,PC
 SG_ D2M_DCDC_RQ_Mode_Set_44 : 12|2@1+ (1,0) [0|3] ""  MBMU,PC
 SG_ D2M_DCDC_Work_State_44 : 14|2@1+ (1,0) [0|3] ""  MBMU,PC
 SG_ D2M_DCDC_AlarmSigl_State_44 : 16|1@1+ (1,0) [0|1] ""  MBMU,PC
 SG_ D2M_DCDC_LVPower_State_44 : 17|1@1+ (1,0) [0|1] ""  MBMU,PC
 SG_ D2M_DCDC_Enableline_State_44 : 18|1@1+ (1,0) [0|1] ""  MBMU,PC
 SG_ D2M_Communication_State_44 : 19|1@1+ (1,0) [0|1] ""  MBMU,PC
 SG_ D2M_SUMDATA1_Reserved1_44 : 20|4@1+ (1,0) [0|15] ""  MBMU,PC
 SG_ D2M_DCDC_PCBTemp_44 : 24|8@1+ (1,-40) [-40|215] "℃"  MBMU,PC
 SG_ D2M_DCDC_MosTemp1_44 : 32|8@1+ (1,-40) [-40|215] "℃"  MBMU,PC
 SG_ D2M_DCDC_MosTemp2_44 : 40|8@1+ (1,-40) [-40|215] "℃"  MBMU,PC
 SG_ D2M_DCDC_TransformerTemp_44 : 48|8@1+ (1,-40) [-40|215] "℃"  MBMU,PC
 SG_ D2M_DCDC_Sleep_State_44 : 56|1@1+ (1,0) [0|1] ""  MBMU,PC
 SG_ D2M_SUMDATA1_Reserved_44 : 57|7@1+ (1,0) [0|127] ""  MBMU,PC

BO_ 2332884845 D2M_SUMDATA1__45: 8 DCDC
 SG_ D2M_SUMDATA1_CRC_45 : 0|8@1+ (1,0) [0|255] ""  MBMU,PC
 SG_ D2M_SUMDATA1_DCDC_Life_45 : 8|4@1+ (1,0) [0|15] ""  MBMU,PC
 SG_ D2M_DCDC_RQ_Mode_Set_45 : 12|2@1+ (1,0) [0|3] ""  MBMU,PC
 SG_ D2M_DCDC_Work_State_45 : 14|2@1+ (1,0) [0|3] ""  MBMU,PC
 SG_ D2M_DCDC_AlarmSigl_State_45 : 16|1@1+ (1,0) [0|1] ""  MBMU,PC
 SG_ D2M_DCDC_LVPower_State_45 : 17|1@1+ (1,0) [0|1] ""  MBMU,PC
 SG_ D2M_DCDC_Enableline_State_45 : 18|1@1+ (1,0) [0|1] ""  MBMU,PC
 SG_ D2M_Communication_State_45 : 19|1@1+ (1,0) [0|1] ""  MBMU,PC
 SG_ D2M_SUMDATA1_Reserved1_45 : 20|4@1+ (1,0) [0|15] ""  MBMU,PC
 SG_ D2M_DCDC_PCBTemp_45 : 24|8@1+ (1,-40) [-40|215] "℃"  MBMU,PC
 SG_ D2M_DCDC_MosTemp1_45 : 32|8@1+ (1,-40) [-40|215] "℃"  MBMU,PC
 SG_ D2M_DCDC_MosTemp2_45 : 40|8@1+ (1,-40) [-40|215] "℃"  MBMU,PC
 SG_ D2M_DCDC_TransformerTemp_45 : 48|8@1+ (1,-40) [-40|215] "℃"  MBMU,PC
 SG_ D2M_DCDC_Sleep_State_45 : 56|1@1+ (1,0) [0|1] ""  MBMU,PC
 SG_ D2M_SUMDATA1_Reserved_45 : 57|7@1+ (1,0) [0|127] ""  MBMU,PC

BO_ 2332884846 D2M_SUMDATA1__46: 8 DCDC
 SG_ D2M_SUMDATA1_CRC_46 : 0|8@1+ (1,0) [0|255] ""  MBMU,PC
 SG_ D2M_SUMDATA1_DCDC_Life_46 : 8|4@1+ (1,0) [0|15] ""  MBMU,PC
 SG_ D2M_DCDC_RQ_Mode_Set_46 : 12|2@1+ (1,0) [0|3] ""  MBMU,PC
 SG_ D2M_DCDC_Work_State_46 : 14|2@1+ (1,0) [0|3] ""  MBMU,PC
 SG_ D2M_DCDC_AlarmSigl_State_46 : 16|1@1+ (1,0) [0|1] ""  MBMU,PC
 SG_ D2M_DCDC_LVPower_State_46 : 17|1@1+ (1,0) [0|1] ""  MBMU,PC
 SG_ D2M_DCDC_Enableline_State_46 : 18|1@1+ (1,0) [0|1] ""  MBMU,PC
 SG_ D2M_Communication_State_46 : 19|1@1+ (1,0) [0|1] ""  MBMU,PC
 SG_ D2M_SUMDATA1_Reserved1_46 : 20|4@1+ (1,0) [0|15] ""  MBMU,PC
 SG_ D2M_DCDC_PCBTemp_46 : 24|8@1+ (1,-40) [-40|215] "℃"  MBMU,PC
 SG_ D2M_DCDC_MosTemp1_46 : 32|8@1+ (1,-40) [-40|215] "℃"  MBMU,PC
 SG_ D2M_DCDC_MosTemp2_46 : 40|8@1+ (1,-40) [-40|215] "℃"  MBMU,PC
 SG_ D2M_DCDC_TransformerTemp_46 : 48|8@1+ (1,-40) [-40|215] "℃"  MBMU,PC
 SG_ D2M_DCDC_Sleep_State_46 : 56|1@1+ (1,0) [0|1] ""  MBMU,PC
 SG_ D2M_SUMDATA1_Reserved_46 : 57|7@1+ (1,0) [0|127] ""  MBMU,PC

BO_ 2332884847 D2M_SUMDATA1__47: 8 DCDC
 SG_ D2M_SUMDATA1_CRC_47 : 0|8@1+ (1,0) [0|255] ""  MBMU,PC
 SG_ D2M_SUMDATA1_DCDC_Life_47 : 8|4@1+ (1,0) [0|15] ""  MBMU,PC
 SG_ D2M_DCDC_RQ_Mode_Set_47 : 12|2@1+ (1,0) [0|3] ""  MBMU,PC
 SG_ D2M_DCDC_Work_State_47 : 14|2@1+ (1,0) [0|3] ""  MBMU,PC
 SG_ D2M_DCDC_AlarmSigl_State_47 : 16|1@1+ (1,0) [0|1] ""  MBMU,PC
 SG_ D2M_DCDC_LVPower_State_47 : 17|1@1+ (1,0) [0|1] ""  MBMU,PC
 SG_ D2M_DCDC_Enableline_State_47 : 18|1@1+ (1,0) [0|1] ""  MBMU,PC
 SG_ D2M_Communication_State_47 : 19|1@1+ (1,0) [0|1] ""  MBMU,PC
 SG_ D2M_SUMDATA1_Reserved1_47 : 20|4@1+ (1,0) [0|15] ""  MBMU,PC
 SG_ D2M_DCDC_PCBTemp_47 : 24|8@1+ (1,-40) [-40|215] "℃"  MBMU,PC
 SG_ D2M_DCDC_MosTemp1_47 : 32|8@1+ (1,-40) [-40|215] "℃"  MBMU,PC
 SG_ D2M_DCDC_MosTemp2_47 : 40|8@1+ (1,-40) [-40|215] "℃"  MBMU,PC
 SG_ D2M_DCDC_TransformerTemp_47 : 48|8@1+ (1,-40) [-40|215] "℃"  MBMU,PC
 SG_ D2M_DCDC_Sleep_State_47 : 56|1@1+ (1,0) [0|1] ""  MBMU,PC
 SG_ D2M_SUMDATA1_Reserved_47 : 57|7@1+ (1,0) [0|127] ""  MBMU,PC

BO_ 2332884848 D2M_SUMDATA1__48: 8 DCDC
 SG_ D2M_SUMDATA1_CRC_48 : 0|8@1+ (1,0) [0|255] ""  MBMU,PC
 SG_ D2M_SUMDATA1_DCDC_Life_48 : 8|4@1+ (1,0) [0|15] ""  MBMU,PC
 SG_ D2M_DCDC_RQ_Mode_Set_48 : 12|2@1+ (1,0) [0|3] ""  MBMU,PC
 SG_ D2M_DCDC_Work_State_48 : 14|2@1+ (1,0) [0|3] ""  MBMU,PC
 SG_ D2M_DCDC_AlarmSigl_State_48 : 16|1@1+ (1,0) [0|1] ""  MBMU,PC
 SG_ D2M_DCDC_LVPower_State_48 : 17|1@1+ (1,0) [0|1] ""  MBMU,PC
 SG_ D2M_DCDC_Enableline_State_48 : 18|1@1+ (1,0) [0|1] ""  MBMU,PC
 SG_ D2M_Communication_State_48 : 19|1@1+ (1,0) [0|1] ""  MBMU,PC
 SG_ D2M_SUMDATA1_Reserved1_48 : 20|4@1+ (1,0) [0|15] ""  MBMU,PC
 SG_ D2M_DCDC_PCBTemp_48 : 24|8@1+ (1,-40) [-40|215] "℃"  MBMU,PC
 SG_ D2M_DCDC_MosTemp1_48 : 32|8@1+ (1,-40) [-40|215] "℃"  MBMU,PC
 SG_ D2M_DCDC_MosTemp2_48 : 40|8@1+ (1,-40) [-40|215] "℃"  MBMU,PC
 SG_ D2M_DCDC_TransformerTemp_48 : 48|8@1+ (1,-40) [-40|215] "℃"  MBMU,PC
 SG_ D2M_DCDC_Sleep_State_48 : 56|1@1+ (1,0) [0|1] ""  MBMU,PC
 SG_ D2M_SUMDATA1_Reserved_48 : 57|7@1+ (1,0) [0|127] ""  MBMU,PC

BO_ 2332884849 D2M_SUMDATA1__49: 8 DCDC
 SG_ D2M_SUMDATA1_CRC_49 : 0|8@1+ (1,0) [0|255] ""  MBMU,PC
 SG_ D2M_SUMDATA1_DCDC_Life_49 : 8|4@1+ (1,0) [0|15] ""  MBMU,PC
 SG_ D2M_DCDC_RQ_Mode_Set_49 : 12|2@1+ (1,0) [0|3] ""  MBMU,PC
 SG_ D2M_DCDC_Work_State_49 : 14|2@1+ (1,0) [0|3] ""  MBMU,PC
 SG_ D2M_DCDC_AlarmSigl_State_49 : 16|1@1+ (1,0) [0|1] ""  MBMU,PC
 SG_ D2M_DCDC_LVPower_State_49 : 17|1@1+ (1,0) [0|1] ""  MBMU,PC
 SG_ D2M_DCDC_Enableline_State_49 : 18|1@1+ (1,0) [0|1] ""  MBMU,PC
 SG_ D2M_Communication_State_49 : 19|1@1+ (1,0) [0|1] ""  MBMU,PC
 SG_ D2M_SUMDATA1_Reserved1_49 : 20|4@1+ (1,0) [0|15] ""  MBMU,PC
 SG_ D2M_DCDC_PCBTemp_49 : 24|8@1+ (1,-40) [-40|215] "℃"  MBMU,PC
 SG_ D2M_DCDC_MosTemp1_49 : 32|8@1+ (1,-40) [-40|215] "℃"  MBMU,PC
 SG_ D2M_DCDC_MosTemp2_49 : 40|8@1+ (1,-40) [-40|215] "℃"  MBMU,PC
 SG_ D2M_DCDC_TransformerTemp_49 : 48|8@1+ (1,-40) [-40|215] "℃"  MBMU,PC
 SG_ D2M_DCDC_Sleep_State_49 : 56|1@1+ (1,0) [0|1] ""  MBMU,PC
 SG_ D2M_SUMDATA1_Reserved_49 : 57|7@1+ (1,0) [0|127] ""  MBMU,PC

BO_ 2332884850 D2M_SUMDATA1__50: 8 DCDC
 SG_ D2M_SUMDATA1_CRC_50 : 0|8@1+ (1,0) [0|255] ""  MBMU,PC
 SG_ D2M_SUMDATA1_DCDC_Life_50 : 8|4@1+ (1,0) [0|15] ""  MBMU,PC
 SG_ D2M_DCDC_RQ_Mode_Set_50 : 12|2@1+ (1,0) [0|3] ""  MBMU,PC
 SG_ D2M_DCDC_Work_State_50 : 14|2@1+ (1,0) [0|3] ""  MBMU,PC
 SG_ D2M_DCDC_AlarmSigl_State_50 : 16|1@1+ (1,0) [0|1] ""  MBMU,PC
 SG_ D2M_DCDC_LVPower_State_50 : 17|1@1+ (1,0) [0|1] ""  MBMU,PC
 SG_ D2M_DCDC_Enableline_State_50 : 18|1@1+ (1,0) [0|1] ""  MBMU,PC
 SG_ D2M_Communication_State_50 : 19|1@1+ (1,0) [0|1] ""  MBMU,PC
 SG_ D2M_SUMDATA1_Reserved1_50 : 20|4@1+ (1,0) [0|15] ""  MBMU,PC
 SG_ D2M_DCDC_PCBTemp_50 : 24|8@1+ (1,-40) [-40|215] "℃"  MBMU,PC
 SG_ D2M_DCDC_MosTemp1_50 : 32|8@1+ (1,-40) [-40|215] "℃"  MBMU,PC
 SG_ D2M_DCDC_MosTemp2_50 : 40|8@1+ (1,-40) [-40|215] "℃"  MBMU,PC
 SG_ D2M_DCDC_TransformerTemp_50 : 48|8@1+ (1,-40) [-40|215] "℃"  MBMU,PC
 SG_ D2M_DCDC_Sleep_State_50 : 56|1@1+ (1,0) [0|1] ""  MBMU,PC
 SG_ D2M_SUMDATA1_Reserved_50 : 57|7@1+ (1,0) [0|127] ""  MBMU,PC

BO_ 2332884851 D2M_SUMDATA1__51: 8 DCDC
 SG_ D2M_SUMDATA1_CRC_51 : 0|8@1+ (1,0) [0|255] ""  MBMU,PC
 SG_ D2M_SUMDATA1_DCDC_Life_51 : 8|4@1+ (1,0) [0|15] ""  MBMU,PC
 SG_ D2M_DCDC_RQ_Mode_Set_51 : 12|2@1+ (1,0) [0|3] ""  MBMU,PC
 SG_ D2M_DCDC_Work_State_51 : 14|2@1+ (1,0) [0|3] ""  MBMU,PC
 SG_ D2M_DCDC_AlarmSigl_State_51 : 16|1@1+ (1,0) [0|1] ""  MBMU,PC
 SG_ D2M_DCDC_LVPower_State_51 : 17|1@1+ (1,0) [0|1] ""  MBMU,PC
 SG_ D2M_DCDC_Enableline_State_51 : 18|1@1+ (1,0) [0|1] ""  MBMU,PC
 SG_ D2M_Communication_State_51 : 19|1@1+ (1,0) [0|1] ""  MBMU,PC
 SG_ D2M_SUMDATA1_Reserved1_51 : 20|4@1+ (1,0) [0|15] ""  MBMU,PC
 SG_ D2M_DCDC_PCBTemp_51 : 24|8@1+ (1,-40) [-40|215] "℃"  MBMU,PC
 SG_ D2M_DCDC_MosTemp1_51 : 32|8@1+ (1,-40) [-40|215] "℃"  MBMU,PC
 SG_ D2M_DCDC_MosTemp2_51 : 40|8@1+ (1,-40) [-40|215] "℃"  MBMU,PC
 SG_ D2M_DCDC_TransformerTemp_51 : 48|8@1+ (1,-40) [-40|215] "℃"  MBMU,PC
 SG_ D2M_DCDC_Sleep_State_51 : 56|1@1+ (1,0) [0|1] ""  MBMU,PC
 SG_ D2M_SUMDATA1_Reserved_51 : 57|7@1+ (1,0) [0|127] ""  MBMU,PC

BO_ 2332884852 D2M_SUMDATA1__52: 8 DCDC
 SG_ D2M_SUMDATA1_CRC_52 : 0|8@1+ (1,0) [0|255] ""  MBMU,PC
 SG_ D2M_SUMDATA1_DCDC_Life_52 : 8|4@1+ (1,0) [0|15] ""  MBMU,PC
 SG_ D2M_DCDC_RQ_Mode_Set_52 : 12|2@1+ (1,0) [0|3] ""  MBMU,PC
 SG_ D2M_DCDC_Work_State_52 : 14|2@1+ (1,0) [0|3] ""  MBMU,PC
 SG_ D2M_DCDC_AlarmSigl_State_52 : 16|1@1+ (1,0) [0|1] ""  MBMU,PC
 SG_ D2M_DCDC_LVPower_State_52 : 17|1@1+ (1,0) [0|1] ""  MBMU,PC
 SG_ D2M_DCDC_Enableline_State_52 : 18|1@1+ (1,0) [0|1] ""  MBMU,PC
 SG_ D2M_Communication_State_52 : 19|1@1+ (1,0) [0|1] ""  MBMU,PC
 SG_ D2M_SUMDATA1_Reserved1_52 : 20|4@1+ (1,0) [0|15] ""  MBMU,PC
 SG_ D2M_DCDC_PCBTemp_52 : 24|8@1+ (1,-40) [-40|215] "℃"  MBMU,PC
 SG_ D2M_DCDC_MosTemp1_52 : 32|8@1+ (1,-40) [-40|215] "℃"  MBMU,PC
 SG_ D2M_DCDC_MosTemp2_52 : 40|8@1+ (1,-40) [-40|215] "℃"  MBMU,PC
 SG_ D2M_DCDC_TransformerTemp_52 : 48|8@1+ (1,-40) [-40|215] "℃"  MBMU,PC
 SG_ D2M_DCDC_Sleep_State_52 : 56|1@1+ (1,0) [0|1] ""  MBMU,PC
 SG_ D2M_SUMDATA1_Reserved_52 : 57|7@1+ (1,0) [0|127] ""  MBMU,PC

CM_ SG_ 2500128381 D2P_Cfg5_Barcode0_61 "DCDC BarCode号第0位";
CM_ SG_ 2500128381 D2P_Cfg5_Barcode1_61 "DCDC BarCode号第1位";
CM_ SG_ 2500128381 D2P_Cfg5_Barcode2_61 "DCDC BarCode号第2位";
CM_ SG_ 2500128381 D2P_Cfg5_Barcode3_61 "DCDC BarCode号第3位";
CM_ SG_ 2500128381 D2P_Cfg5_Barcode4_61 "DCDC BarCode号第4位";
CM_ SG_ 2500128381 D2P_Cfg5_Barcode5_61 "DCDC BarCode号第5位";
CM_ SG_ 2500128381 D2P_Cfg5_Barcode6_61 "DCDC BarCode号第6位";
CM_ SG_ 2500128381 D2P_Cfg5_Barcode7_61 "DCDC BarCode号第7位";
CM_ SG_ 2500128382 D2P_Cfg5_Barcode0_62 "DCDC BarCode号第0位";
CM_ SG_ 2500128382 D2P_Cfg5_Barcode1_62 "DCDC BarCode号第1位";
CM_ SG_ 2500128382 D2P_Cfg5_Barcode2_62 "DCDC BarCode号第2位";
CM_ SG_ 2500128382 D2P_Cfg5_Barcode3_62 "DCDC BarCode号第3位";
CM_ SG_ 2500128382 D2P_Cfg5_Barcode4_62 "DCDC BarCode号第4位";
CM_ SG_ 2500128382 D2P_Cfg5_Barcode5_62 "DCDC BarCode号第5位";
CM_ SG_ 2500128382 D2P_Cfg5_Barcode6_62 "DCDC BarCode号第6位";
CM_ SG_ 2500128382 D2P_Cfg5_Barcode7_62 "DCDC BarCode号第7位";
CM_ SG_ 2500128383 D2P_Cfg5_Barcode0_63 "DCDC BarCode号第0位";
CM_ SG_ 2500128383 D2P_Cfg5_Barcode1_63 "DCDC BarCode号第1位";
CM_ SG_ 2500128383 D2P_Cfg5_Barcode2_63 "DCDC BarCode号第2位";
CM_ SG_ 2500128383 D2P_Cfg5_Barcode3_63 "DCDC BarCode号第3位";
CM_ SG_ 2500128383 D2P_Cfg5_Barcode4_63 "DCDC BarCode号第4位";
CM_ SG_ 2500128383 D2P_Cfg5_Barcode5_63 "DCDC BarCode号第5位";
CM_ SG_ 2500128383 D2P_Cfg5_Barcode6_63 "DCDC BarCode号第6位";
CM_ SG_ 2500128383 D2P_Cfg5_Barcode7_63 "DCDC BarCode号第7位";
CM_ SG_ 2500193857 D2P_WriteOK_Byte0_01 "发送页数写入确认数据帧报文字节0";
CM_ SG_ 2500193857 D2P_WriteOK_Byte1_01 "发送页数写入确认数据帧报文字节1";
CM_ SG_ 2500193857 D2P_WriteOK_Byte2_01 "发送页数写入确认数据帧报文字节2";
CM_ SG_ 2500193857 D2P_WriteOK_Byte3_01 "发送页数写入确认数据帧报文字节3";
CM_ SG_ 2500193857 D2P_WriteOK_Byte4_01 "发送页数写入确认数据帧报文字节4";
CM_ SG_ 2500193857 D2P_WriteOK_Byte5_01 "发送页数写入确认数据帧报文字节5";
CM_ SG_ 2500193857 D2P_WriteOK_Byte6_01 "发送页数写入确认数据帧报文字节6";
CM_ SG_ 2500193857 D2P_WriteOK_Byte7_01 "发送页数写入确认数据帧报文字节7";
CM_ SG_ 2500193858 D2P_WriteOK_Byte0_02 "发送页数写入确认数据帧报文字节0";
CM_ SG_ 2500193858 D2P_WriteOK_Byte1_02 "发送页数写入确认数据帧报文字节1";
CM_ SG_ 2500193858 D2P_WriteOK_Byte2_02 "发送页数写入确认数据帧报文字节2";
CM_ SG_ 2500193858 D2P_WriteOK_Byte3_02 "发送页数写入确认数据帧报文字节3";
CM_ SG_ 2500193858 D2P_WriteOK_Byte4_02 "发送页数写入确认数据帧报文字节4";
CM_ SG_ 2500193858 D2P_WriteOK_Byte5_02 "发送页数写入确认数据帧报文字节5";
CM_ SG_ 2500193858 D2P_WriteOK_Byte6_02 "发送页数写入确认数据帧报文字节6";
CM_ SG_ 2500193858 D2P_WriteOK_Byte7_02 "发送页数写入确认数据帧报文字节7";
CM_ SG_ 2500193859 D2P_WriteOK_Byte0_03 "发送页数写入确认数据帧报文字节0";
CM_ SG_ 2500193859 D2P_WriteOK_Byte1_03 "发送页数写入确认数据帧报文字节1";
CM_ SG_ 2500193859 D2P_WriteOK_Byte2_03 "发送页数写入确认数据帧报文字节2";
CM_ SG_ 2500193859 D2P_WriteOK_Byte3_03 "发送页数写入确认数据帧报文字节3";
CM_ SG_ 2500193859 D2P_WriteOK_Byte4_03 "发送页数写入确认数据帧报文字节4";
CM_ SG_ 2500193859 D2P_WriteOK_Byte5_03 "发送页数写入确认数据帧报文字节5";
CM_ SG_ 2500193859 D2P_WriteOK_Byte6_03 "发送页数写入确认数据帧报文字节6";
CM_ SG_ 2500193859 D2P_WriteOK_Byte7_03 "发送页数写入确认数据帧报文字节7";
CM_ SG_ 2500193860 D2P_WriteOK_Byte0_04 "发送页数写入确认数据帧报文字节0";
CM_ SG_ 2500193860 D2P_WriteOK_Byte1_04 "发送页数写入确认数据帧报文字节1";
CM_ SG_ 2500193860 D2P_WriteOK_Byte2_04 "发送页数写入确认数据帧报文字节2";
CM_ SG_ 2500193860 D2P_WriteOK_Byte3_04 "发送页数写入确认数据帧报文字节3";
CM_ SG_ 2500193860 D2P_WriteOK_Byte4_04 "发送页数写入确认数据帧报文字节4";
CM_ SG_ 2500193860 D2P_WriteOK_Byte5_04 "发送页数写入确认数据帧报文字节5";
CM_ SG_ 2500193860 D2P_WriteOK_Byte6_04 "发送页数写入确认数据帧报文字节6";
CM_ SG_ 2500193860 D2P_WriteOK_Byte7_04 "发送页数写入确认数据帧报文字节7";
CM_ SG_ 2500193861 D2P_WriteOK_Byte0_05 "发送页数写入确认数据帧报文字节0";
CM_ SG_ 2500193861 D2P_WriteOK_Byte1_05 "发送页数写入确认数据帧报文字节1";
CM_ SG_ 2500193861 D2P_WriteOK_Byte2_05 "发送页数写入确认数据帧报文字节2";
CM_ SG_ 2500193861 D2P_WriteOK_Byte3_05 "发送页数写入确认数据帧报文字节3";
CM_ SG_ 2500193861 D2P_WriteOK_Byte4_05 "发送页数写入确认数据帧报文字节4";
CM_ SG_ 2500193861 D2P_WriteOK_Byte5_05 "发送页数写入确认数据帧报文字节5";
CM_ SG_ 2500193861 D2P_WriteOK_Byte6_05 "发送页数写入确认数据帧报文字节6";
CM_ SG_ 2500193861 D2P_WriteOK_Byte7_05 "发送页数写入确认数据帧报文字节7";
CM_ SG_ 2500193862 D2P_WriteOK_Byte0_06 "发送页数写入确认数据帧报文字节0";
CM_ SG_ 2500193862 D2P_WriteOK_Byte1_06 "发送页数写入确认数据帧报文字节1";
CM_ SG_ 2500193862 D2P_WriteOK_Byte2_06 "发送页数写入确认数据帧报文字节2";
CM_ SG_ 2500193862 D2P_WriteOK_Byte3_06 "发送页数写入确认数据帧报文字节3";
CM_ SG_ 2500193862 D2P_WriteOK_Byte4_06 "发送页数写入确认数据帧报文字节4";
CM_ SG_ 2500193862 D2P_WriteOK_Byte5_06 "发送页数写入确认数据帧报文字节5";
CM_ SG_ 2500193862 D2P_WriteOK_Byte6_06 "发送页数写入确认数据帧报文字节6";
CM_ SG_ 2500193862 D2P_WriteOK_Byte7_06 "发送页数写入确认数据帧报文字节7";
CM_ SG_ 2500193863 D2P_WriteOK_Byte0_07 "发送页数写入确认数据帧报文字节0";
CM_ SG_ 2500193863 D2P_WriteOK_Byte1_07 "发送页数写入确认数据帧报文字节1";
CM_ SG_ 2500193863 D2P_WriteOK_Byte2_07 "发送页数写入确认数据帧报文字节2";
CM_ SG_ 2500193863 D2P_WriteOK_Byte3_07 "发送页数写入确认数据帧报文字节3";
CM_ SG_ 2500193863 D2P_WriteOK_Byte4_07 "发送页数写入确认数据帧报文字节4";
CM_ SG_ 2500193863 D2P_WriteOK_Byte5_07 "发送页数写入确认数据帧报文字节5";
CM_ SG_ 2500193863 D2P_WriteOK_Byte6_07 "发送页数写入确认数据帧报文字节6";
CM_ SG_ 2500193863 D2P_WriteOK_Byte7_07 "发送页数写入确认数据帧报文字节7";
CM_ SG_ 2500193864 D2P_WriteOK_Byte0_08 "发送页数写入确认数据帧报文字节0";
CM_ SG_ 2500193864 D2P_WriteOK_Byte1_08 "发送页数写入确认数据帧报文字节1";
CM_ SG_ 2500193864 D2P_WriteOK_Byte2_08 "发送页数写入确认数据帧报文字节2";
CM_ SG_ 2500193864 D2P_WriteOK_Byte3_08 "发送页数写入确认数据帧报文字节3";
CM_ SG_ 2500193864 D2P_WriteOK_Byte4_08 "发送页数写入确认数据帧报文字节4";
CM_ SG_ 2500193864 D2P_WriteOK_Byte5_08 "发送页数写入确认数据帧报文字节5";
CM_ SG_ 2500193864 D2P_WriteOK_Byte6_08 "发送页数写入确认数据帧报文字节6";
CM_ SG_ 2500193864 D2P_WriteOK_Byte7_08 "发送页数写入确认数据帧报文字节7";
CM_ SG_ 2500193865 D2P_WriteOK_Byte0_09 "发送页数写入确认数据帧报文字节0";
CM_ SG_ 2500193865 D2P_WriteOK_Byte1_09 "发送页数写入确认数据帧报文字节1";
CM_ SG_ 2500193865 D2P_WriteOK_Byte2_09 "发送页数写入确认数据帧报文字节2";
CM_ SG_ 2500193865 D2P_WriteOK_Byte3_09 "发送页数写入确认数据帧报文字节3";
CM_ SG_ 2500193865 D2P_WriteOK_Byte4_09 "发送页数写入确认数据帧报文字节4";
CM_ SG_ 2500193865 D2P_WriteOK_Byte5_09 "发送页数写入确认数据帧报文字节5";
CM_ SG_ 2500193865 D2P_WriteOK_Byte6_09 "发送页数写入确认数据帧报文字节6";
CM_ SG_ 2500193865 D2P_WriteOK_Byte7_09 "发送页数写入确认数据帧报文字节7";
CM_ SG_ 2500193866 D2P_WriteOK_Byte0_10 "发送页数写入确认数据帧报文字节0";
CM_ SG_ 2500193866 D2P_WriteOK_Byte1_10 "发送页数写入确认数据帧报文字节1";
CM_ SG_ 2500193866 D2P_WriteOK_Byte2_10 "发送页数写入确认数据帧报文字节2";
CM_ SG_ 2500193866 D2P_WriteOK_Byte3_10 "发送页数写入确认数据帧报文字节3";
CM_ SG_ 2500193866 D2P_WriteOK_Byte4_10 "发送页数写入确认数据帧报文字节4";
CM_ SG_ 2500193866 D2P_WriteOK_Byte5_10 "发送页数写入确认数据帧报文字节5";
CM_ SG_ 2500193866 D2P_WriteOK_Byte6_10 "发送页数写入确认数据帧报文字节6";
CM_ SG_ 2500193866 D2P_WriteOK_Byte7_10 "发送页数写入确认数据帧报文字节7";
CM_ SG_ 2500193867 D2P_WriteOK_Byte0_11 "发送页数写入确认数据帧报文字节0";
CM_ SG_ 2500193867 D2P_WriteOK_Byte1_11 "发送页数写入确认数据帧报文字节1";
CM_ SG_ 2500193867 D2P_WriteOK_Byte2_11 "发送页数写入确认数据帧报文字节2";
CM_ SG_ 2500193867 D2P_WriteOK_Byte3_11 "发送页数写入确认数据帧报文字节3";
CM_ SG_ 2500193867 D2P_WriteOK_Byte4_11 "发送页数写入确认数据帧报文字节4";
CM_ SG_ 2500193867 D2P_WriteOK_Byte5_11 "发送页数写入确认数据帧报文字节5";
CM_ SG_ 2500193867 D2P_WriteOK_Byte6_11 "发送页数写入确认数据帧报文字节6";
CM_ SG_ 2500193867 D2P_WriteOK_Byte7_11 "发送页数写入确认数据帧报文字节7";
CM_ SG_ 2500193868 D2P_WriteOK_Byte0_12 "发送页数写入确认数据帧报文字节0";
CM_ SG_ 2500193868 D2P_WriteOK_Byte1_12 "发送页数写入确认数据帧报文字节1";
CM_ SG_ 2500193868 D2P_WriteOK_Byte2_12 "发送页数写入确认数据帧报文字节2";
CM_ SG_ 2500193868 D2P_WriteOK_Byte3_12 "发送页数写入确认数据帧报文字节3";
CM_ SG_ 2500193868 D2P_WriteOK_Byte4_12 "发送页数写入确认数据帧报文字节4";
CM_ SG_ 2500193868 D2P_WriteOK_Byte5_12 "发送页数写入确认数据帧报文字节5";
CM_ SG_ 2500193868 D2P_WriteOK_Byte6_12 "发送页数写入确认数据帧报文字节6";
CM_ SG_ 2500193868 D2P_WriteOK_Byte7_12 "发送页数写入确认数据帧报文字节7";
CM_ SG_ 2500193869 D2P_WriteOK_Byte0_13 "发送页数写入确认数据帧报文字节0";
CM_ SG_ 2500193869 D2P_WriteOK_Byte1_13 "发送页数写入确认数据帧报文字节1";
CM_ SG_ 2500193869 D2P_WriteOK_Byte2_13 "发送页数写入确认数据帧报文字节2";
CM_ SG_ 2500193869 D2P_WriteOK_Byte3_13 "发送页数写入确认数据帧报文字节3";
CM_ SG_ 2500193869 D2P_WriteOK_Byte4_13 "发送页数写入确认数据帧报文字节4";
CM_ SG_ 2500193869 D2P_WriteOK_Byte5_13 "发送页数写入确认数据帧报文字节5";
CM_ SG_ 2500193869 D2P_WriteOK_Byte6_13 "发送页数写入确认数据帧报文字节6";
CM_ SG_ 2500193869 D2P_WriteOK_Byte7_13 "发送页数写入确认数据帧报文字节7";
CM_ SG_ 2500193870 D2P_WriteOK_Byte0_14 "发送页数写入确认数据帧报文字节0";
CM_ SG_ 2500193870 D2P_WriteOK_Byte1_14 "发送页数写入确认数据帧报文字节1";
CM_ SG_ 2500193870 D2P_WriteOK_Byte2_14 "发送页数写入确认数据帧报文字节2";
CM_ SG_ 2500193870 D2P_WriteOK_Byte3_14 "发送页数写入确认数据帧报文字节3";
CM_ SG_ 2500193870 D2P_WriteOK_Byte4_14 "发送页数写入确认数据帧报文字节4";
CM_ SG_ 2500193870 D2P_WriteOK_Byte5_14 "发送页数写入确认数据帧报文字节5";
CM_ SG_ 2500193870 D2P_WriteOK_Byte6_14 "发送页数写入确认数据帧报文字节6";
CM_ SG_ 2500193870 D2P_WriteOK_Byte7_14 "发送页数写入确认数据帧报文字节7";
CM_ SG_ 2500193871 D2P_WriteOK_Byte0_15 "发送页数写入确认数据帧报文字节0";
CM_ SG_ 2500193871 D2P_WriteOK_Byte1_15 "发送页数写入确认数据帧报文字节1";
CM_ SG_ 2500193871 D2P_WriteOK_Byte2_15 "发送页数写入确认数据帧报文字节2";
CM_ SG_ 2500193871 D2P_WriteOK_Byte3_15 "发送页数写入确认数据帧报文字节3";
CM_ SG_ 2500193871 D2P_WriteOK_Byte4_15 "发送页数写入确认数据帧报文字节4";
CM_ SG_ 2500193871 D2P_WriteOK_Byte5_15 "发送页数写入确认数据帧报文字节5";
CM_ SG_ 2500193871 D2P_WriteOK_Byte6_15 "发送页数写入确认数据帧报文字节6";
CM_ SG_ 2500193871 D2P_WriteOK_Byte7_15 "发送页数写入确认数据帧报文字节7";
CM_ SG_ 2500193872 D2P_WriteOK_Byte0_16 "发送页数写入确认数据帧报文字节0";
CM_ SG_ 2500193872 D2P_WriteOK_Byte1_16 "发送页数写入确认数据帧报文字节1";
CM_ SG_ 2500193872 D2P_WriteOK_Byte2_16 "发送页数写入确认数据帧报文字节2";
CM_ SG_ 2500193872 D2P_WriteOK_Byte3_16 "发送页数写入确认数据帧报文字节3";
CM_ SG_ 2500193872 D2P_WriteOK_Byte4_16 "发送页数写入确认数据帧报文字节4";
CM_ SG_ 2500193872 D2P_WriteOK_Byte5_16 "发送页数写入确认数据帧报文字节5";
CM_ SG_ 2500193872 D2P_WriteOK_Byte6_16 "发送页数写入确认数据帧报文字节6";
CM_ SG_ 2500193872 D2P_WriteOK_Byte7_16 "发送页数写入确认数据帧报文字节7";
CM_ SG_ 2500193873 D2P_WriteOK_Byte0_17 "发送页数写入确认数据帧报文字节0";
CM_ SG_ 2500193873 D2P_WriteOK_Byte1_17 "发送页数写入确认数据帧报文字节1";
CM_ SG_ 2500193873 D2P_WriteOK_Byte2_17 "发送页数写入确认数据帧报文字节2";
CM_ SG_ 2500193873 D2P_WriteOK_Byte3_17 "发送页数写入确认数据帧报文字节3";
CM_ SG_ 2500193873 D2P_WriteOK_Byte4_17 "发送页数写入确认数据帧报文字节4";
CM_ SG_ 2500193873 D2P_WriteOK_Byte5_17 "发送页数写入确认数据帧报文字节5";
CM_ SG_ 2500193873 D2P_WriteOK_Byte6_17 "发送页数写入确认数据帧报文字节6";
CM_ SG_ 2500193873 D2P_WriteOK_Byte7_17 "发送页数写入确认数据帧报文字节7";
CM_ SG_ 2500193874 D2P_WriteOK_Byte0_18 "发送页数写入确认数据帧报文字节0";
CM_ SG_ 2500193874 D2P_WriteOK_Byte1_18 "发送页数写入确认数据帧报文字节1";
CM_ SG_ 2500193874 D2P_WriteOK_Byte2_18 "发送页数写入确认数据帧报文字节2";
CM_ SG_ 2500193874 D2P_WriteOK_Byte3_18 "发送页数写入确认数据帧报文字节3";
CM_ SG_ 2500193874 D2P_WriteOK_Byte4_18 "发送页数写入确认数据帧报文字节4";
CM_ SG_ 2500193874 D2P_WriteOK_Byte5_18 "发送页数写入确认数据帧报文字节5";
CM_ SG_ 2500193874 D2P_WriteOK_Byte6_18 "发送页数写入确认数据帧报文字节6";
CM_ SG_ 2500193874 D2P_WriteOK_Byte7_18 "发送页数写入确认数据帧报文字节7";
CM_ SG_ 2500193875 D2P_WriteOK_Byte0_19 "发送页数写入确认数据帧报文字节0";
CM_ SG_ 2500193875 D2P_WriteOK_Byte1_19 "发送页数写入确认数据帧报文字节1";
CM_ SG_ 2500193875 D2P_WriteOK_Byte2_19 "发送页数写入确认数据帧报文字节2";
CM_ SG_ 2500193875 D2P_WriteOK_Byte3_19 "发送页数写入确认数据帧报文字节3";
CM_ SG_ 2500193875 D2P_WriteOK_Byte4_19 "发送页数写入确认数据帧报文字节4";
CM_ SG_ 2500193875 D2P_WriteOK_Byte5_19 "发送页数写入确认数据帧报文字节5";
CM_ SG_ 2500193875 D2P_WriteOK_Byte6_19 "发送页数写入确认数据帧报文字节6";
CM_ SG_ 2500193875 D2P_WriteOK_Byte7_19 "发送页数写入确认数据帧报文字节7";
CM_ SG_ 2500193876 D2P_WriteOK_Byte0_20 "发送页数写入确认数据帧报文字节0";
CM_ SG_ 2500193876 D2P_WriteOK_Byte1_20 "发送页数写入确认数据帧报文字节1";
CM_ SG_ 2500193876 D2P_WriteOK_Byte2_20 "发送页数写入确认数据帧报文字节2";
CM_ SG_ 2500193876 D2P_WriteOK_Byte3_20 "发送页数写入确认数据帧报文字节3";
CM_ SG_ 2500193876 D2P_WriteOK_Byte4_20 "发送页数写入确认数据帧报文字节4";
CM_ SG_ 2500193876 D2P_WriteOK_Byte5_20 "发送页数写入确认数据帧报文字节5";
CM_ SG_ 2500193876 D2P_WriteOK_Byte6_20 "发送页数写入确认数据帧报文字节6";
CM_ SG_ 2500193876 D2P_WriteOK_Byte7_20 "发送页数写入确认数据帧报文字节7";
CM_ SG_ 2500193877 D2P_WriteOK_Byte0_21 "发送页数写入确认数据帧报文字节0";
CM_ SG_ 2500193877 D2P_WriteOK_Byte1_21 "发送页数写入确认数据帧报文字节1";
CM_ SG_ 2500193877 D2P_WriteOK_Byte2_21 "发送页数写入确认数据帧报文字节2";
CM_ SG_ 2500193877 D2P_WriteOK_Byte3_21 "发送页数写入确认数据帧报文字节3";
CM_ SG_ 2500193877 D2P_WriteOK_Byte4_21 "发送页数写入确认数据帧报文字节4";
CM_ SG_ 2500193877 D2P_WriteOK_Byte5_21 "发送页数写入确认数据帧报文字节5";
CM_ SG_ 2500193877 D2P_WriteOK_Byte6_21 "发送页数写入确认数据帧报文字节6";
CM_ SG_ 2500193877 D2P_WriteOK_Byte7_21 "发送页数写入确认数据帧报文字节7";
CM_ SG_ 2500193878 D2P_WriteOK_Byte0_22 "发送页数写入确认数据帧报文字节0";
CM_ SG_ 2500193878 D2P_WriteOK_Byte1_22 "发送页数写入确认数据帧报文字节1";
CM_ SG_ 2500193878 D2P_WriteOK_Byte2_22 "发送页数写入确认数据帧报文字节2";
CM_ SG_ 2500193878 D2P_WriteOK_Byte3_22 "发送页数写入确认数据帧报文字节3";
CM_ SG_ 2500193878 D2P_WriteOK_Byte4_22 "发送页数写入确认数据帧报文字节4";
CM_ SG_ 2500193878 D2P_WriteOK_Byte5_22 "发送页数写入确认数据帧报文字节5";
CM_ SG_ 2500193878 D2P_WriteOK_Byte6_22 "发送页数写入确认数据帧报文字节6";
CM_ SG_ 2500193878 D2P_WriteOK_Byte7_22 "发送页数写入确认数据帧报文字节7";
CM_ SG_ 2500193879 D2P_WriteOK_Byte0_23 "发送页数写入确认数据帧报文字节0";
CM_ SG_ 2500193879 D2P_WriteOK_Byte1_23 "发送页数写入确认数据帧报文字节1";
CM_ SG_ 2500193879 D2P_WriteOK_Byte2_23 "发送页数写入确认数据帧报文字节2";
CM_ SG_ 2500193879 D2P_WriteOK_Byte3_23 "发送页数写入确认数据帧报文字节3";
CM_ SG_ 2500193879 D2P_WriteOK_Byte4_23 "发送页数写入确认数据帧报文字节4";
CM_ SG_ 2500193879 D2P_WriteOK_Byte5_23 "发送页数写入确认数据帧报文字节5";
CM_ SG_ 2500193879 D2P_WriteOK_Byte6_23 "发送页数写入确认数据帧报文字节6";
CM_ SG_ 2500193879 D2P_WriteOK_Byte7_23 "发送页数写入确认数据帧报文字节7";
CM_ SG_ 2500193880 D2P_WriteOK_Byte0_24 "发送页数写入确认数据帧报文字节0";
CM_ SG_ 2500193880 D2P_WriteOK_Byte1_24 "发送页数写入确认数据帧报文字节1";
CM_ SG_ 2500193880 D2P_WriteOK_Byte2_24 "发送页数写入确认数据帧报文字节2";
CM_ SG_ 2500193880 D2P_WriteOK_Byte3_24 "发送页数写入确认数据帧报文字节3";
CM_ SG_ 2500193880 D2P_WriteOK_Byte4_24 "发送页数写入确认数据帧报文字节4";
CM_ SG_ 2500193880 D2P_WriteOK_Byte5_24 "发送页数写入确认数据帧报文字节5";
CM_ SG_ 2500193880 D2P_WriteOK_Byte6_24 "发送页数写入确认数据帧报文字节6";
CM_ SG_ 2500193880 D2P_WriteOK_Byte7_24 "发送页数写入确认数据帧报文字节7";
CM_ SG_ 2500193881 D2P_WriteOK_Byte0_25 "发送页数写入确认数据帧报文字节0";
CM_ SG_ 2500193881 D2P_WriteOK_Byte1_25 "发送页数写入确认数据帧报文字节1";
CM_ SG_ 2500193881 D2P_WriteOK_Byte2_25 "发送页数写入确认数据帧报文字节2";
CM_ SG_ 2500193881 D2P_WriteOK_Byte3_25 "发送页数写入确认数据帧报文字节3";
CM_ SG_ 2500193881 D2P_WriteOK_Byte4_25 "发送页数写入确认数据帧报文字节4";
CM_ SG_ 2500193881 D2P_WriteOK_Byte5_25 "发送页数写入确认数据帧报文字节5";
CM_ SG_ 2500193881 D2P_WriteOK_Byte6_25 "发送页数写入确认数据帧报文字节6";
CM_ SG_ 2500193881 D2P_WriteOK_Byte7_25 "发送页数写入确认数据帧报文字节7";
CM_ SG_ 2500193882 D2P_WriteOK_Byte0_26 "发送页数写入确认数据帧报文字节0";
CM_ SG_ 2500193882 D2P_WriteOK_Byte1_26 "发送页数写入确认数据帧报文字节1";
CM_ SG_ 2500193882 D2P_WriteOK_Byte2_26 "发送页数写入确认数据帧报文字节2";
CM_ SG_ 2500193882 D2P_WriteOK_Byte3_26 "发送页数写入确认数据帧报文字节3";
CM_ SG_ 2500193882 D2P_WriteOK_Byte4_26 "发送页数写入确认数据帧报文字节4";
CM_ SG_ 2500193882 D2P_WriteOK_Byte5_26 "发送页数写入确认数据帧报文字节5";
CM_ SG_ 2500193882 D2P_WriteOK_Byte6_26 "发送页数写入确认数据帧报文字节6";
CM_ SG_ 2500193882 D2P_WriteOK_Byte7_26 "发送页数写入确认数据帧报文字节7";
CM_ SG_ 2500193883 D2P_WriteOK_Byte0_27 "发送页数写入确认数据帧报文字节0";
CM_ SG_ 2500193883 D2P_WriteOK_Byte1_27 "发送页数写入确认数据帧报文字节1";
CM_ SG_ 2500193883 D2P_WriteOK_Byte2_27 "发送页数写入确认数据帧报文字节2";
CM_ SG_ 2500193883 D2P_WriteOK_Byte3_27 "发送页数写入确认数据帧报文字节3";
CM_ SG_ 2500193883 D2P_WriteOK_Byte4_27 "发送页数写入确认数据帧报文字节4";
CM_ SG_ 2500193883 D2P_WriteOK_Byte5_27 "发送页数写入确认数据帧报文字节5";
CM_ SG_ 2500193883 D2P_WriteOK_Byte6_27 "发送页数写入确认数据帧报文字节6";
CM_ SG_ 2500193883 D2P_WriteOK_Byte7_27 "发送页数写入确认数据帧报文字节7";
CM_ SG_ 2500193884 D2P_WriteOK_Byte0_28 "发送页数写入确认数据帧报文字节0";
CM_ SG_ 2500193884 D2P_WriteOK_Byte1_28 "发送页数写入确认数据帧报文字节1";
CM_ SG_ 2500193884 D2P_WriteOK_Byte2_28 "发送页数写入确认数据帧报文字节2";
CM_ SG_ 2500193884 D2P_WriteOK_Byte3_28 "发送页数写入确认数据帧报文字节3";
CM_ SG_ 2500193884 D2P_WriteOK_Byte4_28 "发送页数写入确认数据帧报文字节4";
CM_ SG_ 2500193884 D2P_WriteOK_Byte5_28 "发送页数写入确认数据帧报文字节5";
CM_ SG_ 2500193884 D2P_WriteOK_Byte6_28 "发送页数写入确认数据帧报文字节6";
CM_ SG_ 2500193884 D2P_WriteOK_Byte7_28 "发送页数写入确认数据帧报文字节7";
CM_ SG_ 2500193885 D2P_WriteOK_Byte0_29 "发送页数写入确认数据帧报文字节0";
CM_ SG_ 2500193885 D2P_WriteOK_Byte1_29 "发送页数写入确认数据帧报文字节1";
CM_ SG_ 2500193885 D2P_WriteOK_Byte2_29 "发送页数写入确认数据帧报文字节2";
CM_ SG_ 2500193885 D2P_WriteOK_Byte3_29 "发送页数写入确认数据帧报文字节3";
CM_ SG_ 2500193885 D2P_WriteOK_Byte4_29 "发送页数写入确认数据帧报文字节4";
CM_ SG_ 2500193885 D2P_WriteOK_Byte5_29 "发送页数写入确认数据帧报文字节5";
CM_ SG_ 2500193885 D2P_WriteOK_Byte6_29 "发送页数写入确认数据帧报文字节6";
CM_ SG_ 2500193885 D2P_WriteOK_Byte7_29 "发送页数写入确认数据帧报文字节7";
CM_ SG_ 2500193886 D2P_WriteOK_Byte0_30 "发送页数写入确认数据帧报文字节0";
CM_ SG_ 2500193886 D2P_WriteOK_Byte1_30 "发送页数写入确认数据帧报文字节1";
CM_ SG_ 2500193886 D2P_WriteOK_Byte2_30 "发送页数写入确认数据帧报文字节2";
CM_ SG_ 2500193886 D2P_WriteOK_Byte3_30 "发送页数写入确认数据帧报文字节3";
CM_ SG_ 2500193886 D2P_WriteOK_Byte4_30 "发送页数写入确认数据帧报文字节4";
CM_ SG_ 2500193886 D2P_WriteOK_Byte5_30 "发送页数写入确认数据帧报文字节5";
CM_ SG_ 2500193886 D2P_WriteOK_Byte6_30 "发送页数写入确认数据帧报文字节6";
CM_ SG_ 2500193886 D2P_WriteOK_Byte7_30 "发送页数写入确认数据帧报文字节7";
CM_ SG_ 2500193887 D2P_WriteOK_Byte0_31 "发送页数写入确认数据帧报文字节0";
CM_ SG_ 2500193887 D2P_WriteOK_Byte1_31 "发送页数写入确认数据帧报文字节1";
CM_ SG_ 2500193887 D2P_WriteOK_Byte2_31 "发送页数写入确认数据帧报文字节2";
CM_ SG_ 2500193887 D2P_WriteOK_Byte3_31 "发送页数写入确认数据帧报文字节3";
CM_ SG_ 2500193887 D2P_WriteOK_Byte4_31 "发送页数写入确认数据帧报文字节4";
CM_ SG_ 2500193887 D2P_WriteOK_Byte5_31 "发送页数写入确认数据帧报文字节5";
CM_ SG_ 2500193887 D2P_WriteOK_Byte6_31 "发送页数写入确认数据帧报文字节6";
CM_ SG_ 2500193887 D2P_WriteOK_Byte7_31 "发送页数写入确认数据帧报文字节7";
CM_ SG_ 2500193888 D2P_WriteOK_Byte0_32 "发送页数写入确认数据帧报文字节0";
CM_ SG_ 2500193888 D2P_WriteOK_Byte1_32 "发送页数写入确认数据帧报文字节1";
CM_ SG_ 2500193888 D2P_WriteOK_Byte2_32 "发送页数写入确认数据帧报文字节2";
CM_ SG_ 2500193888 D2P_WriteOK_Byte3_32 "发送页数写入确认数据帧报文字节3";
CM_ SG_ 2500193888 D2P_WriteOK_Byte4_32 "发送页数写入确认数据帧报文字节4";
CM_ SG_ 2500193888 D2P_WriteOK_Byte5_32 "发送页数写入确认数据帧报文字节5";
CM_ SG_ 2500193888 D2P_WriteOK_Byte6_32 "发送页数写入确认数据帧报文字节6";
CM_ SG_ 2500193888 D2P_WriteOK_Byte7_32 "发送页数写入确认数据帧报文字节7";
CM_ SG_ 2500193889 D2P_WriteOK_Byte0_33 "发送页数写入确认数据帧报文字节0";
CM_ SG_ 2500193889 D2P_WriteOK_Byte1_33 "发送页数写入确认数据帧报文字节1";
CM_ SG_ 2500193889 D2P_WriteOK_Byte2_33 "发送页数写入确认数据帧报文字节2";
CM_ SG_ 2500193889 D2P_WriteOK_Byte3_33 "发送页数写入确认数据帧报文字节3";
CM_ SG_ 2500193889 D2P_WriteOK_Byte4_33 "发送页数写入确认数据帧报文字节4";
CM_ SG_ 2500193889 D2P_WriteOK_Byte5_33 "发送页数写入确认数据帧报文字节5";
CM_ SG_ 2500193889 D2P_WriteOK_Byte6_33 "发送页数写入确认数据帧报文字节6";
CM_ SG_ 2500193889 D2P_WriteOK_Byte7_33 "发送页数写入确认数据帧报文字节7";
CM_ SG_ 2500193890 D2P_WriteOK_Byte0_34 "发送页数写入确认数据帧报文字节0";
CM_ SG_ 2500193890 D2P_WriteOK_Byte1_34 "发送页数写入确认数据帧报文字节1";
CM_ SG_ 2500193890 D2P_WriteOK_Byte2_34 "发送页数写入确认数据帧报文字节2";
CM_ SG_ 2500193890 D2P_WriteOK_Byte3_34 "发送页数写入确认数据帧报文字节3";
CM_ SG_ 2500193890 D2P_WriteOK_Byte4_34 "发送页数写入确认数据帧报文字节4";
CM_ SG_ 2500193890 D2P_WriteOK_Byte5_34 "发送页数写入确认数据帧报文字节5";
CM_ SG_ 2500193890 D2P_WriteOK_Byte6_34 "发送页数写入确认数据帧报文字节6";
CM_ SG_ 2500193890 D2P_WriteOK_Byte7_34 "发送页数写入确认数据帧报文字节7";
CM_ SG_ 2500193891 D2P_WriteOK_Byte0_35 "发送页数写入确认数据帧报文字节0";
CM_ SG_ 2500193891 D2P_WriteOK_Byte1_35 "发送页数写入确认数据帧报文字节1";
CM_ SG_ 2500193891 D2P_WriteOK_Byte2_35 "发送页数写入确认数据帧报文字节2";
CM_ SG_ 2500193891 D2P_WriteOK_Byte3_35 "发送页数写入确认数据帧报文字节3";
CM_ SG_ 2500193891 D2P_WriteOK_Byte4_35 "发送页数写入确认数据帧报文字节4";
CM_ SG_ 2500193891 D2P_WriteOK_Byte5_35 "发送页数写入确认数据帧报文字节5";
CM_ SG_ 2500193891 D2P_WriteOK_Byte6_35 "发送页数写入确认数据帧报文字节6";
CM_ SG_ 2500193891 D2P_WriteOK_Byte7_35 "发送页数写入确认数据帧报文字节7";
CM_ SG_ 2500193892 D2P_WriteOK_Byte0_36 "发送页数写入确认数据帧报文字节0";
CM_ SG_ 2500193892 D2P_WriteOK_Byte1_36 "发送页数写入确认数据帧报文字节1";
CM_ SG_ 2500193892 D2P_WriteOK_Byte2_36 "发送页数写入确认数据帧报文字节2";
CM_ SG_ 2500193892 D2P_WriteOK_Byte3_36 "发送页数写入确认数据帧报文字节3";
CM_ SG_ 2500193892 D2P_WriteOK_Byte4_36 "发送页数写入确认数据帧报文字节4";
CM_ SG_ 2500193892 D2P_WriteOK_Byte5_36 "发送页数写入确认数据帧报文字节5";
CM_ SG_ 2500193892 D2P_WriteOK_Byte6_36 "发送页数写入确认数据帧报文字节6";
CM_ SG_ 2500193892 D2P_WriteOK_Byte7_36 "发送页数写入确认数据帧报文字节7";
CM_ SG_ 2500193893 D2P_WriteOK_Byte0_37 "发送页数写入确认数据帧报文字节0";
CM_ SG_ 2500193893 D2P_WriteOK_Byte1_37 "发送页数写入确认数据帧报文字节1";
CM_ SG_ 2500193893 D2P_WriteOK_Byte2_37 "发送页数写入确认数据帧报文字节2";
CM_ SG_ 2500193893 D2P_WriteOK_Byte3_37 "发送页数写入确认数据帧报文字节3";
CM_ SG_ 2500193893 D2P_WriteOK_Byte4_37 "发送页数写入确认数据帧报文字节4";
CM_ SG_ 2500193893 D2P_WriteOK_Byte5_37 "发送页数写入确认数据帧报文字节5";
CM_ SG_ 2500193893 D2P_WriteOK_Byte6_37 "发送页数写入确认数据帧报文字节6";
CM_ SG_ 2500193893 D2P_WriteOK_Byte7_37 "发送页数写入确认数据帧报文字节7";
CM_ SG_ 2500193894 D2P_WriteOK_Byte0_38 "发送页数写入确认数据帧报文字节0";
CM_ SG_ 2500193894 D2P_WriteOK_Byte1_38 "发送页数写入确认数据帧报文字节1";
CM_ SG_ 2500193894 D2P_WriteOK_Byte2_38 "发送页数写入确认数据帧报文字节2";
CM_ SG_ 2500193894 D2P_WriteOK_Byte3_38 "发送页数写入确认数据帧报文字节3";
CM_ SG_ 2500193894 D2P_WriteOK_Byte4_38 "发送页数写入确认数据帧报文字节4";
CM_ SG_ 2500193894 D2P_WriteOK_Byte5_38 "发送页数写入确认数据帧报文字节5";
CM_ SG_ 2500193894 D2P_WriteOK_Byte6_38 "发送页数写入确认数据帧报文字节6";
CM_ SG_ 2500193894 D2P_WriteOK_Byte7_38 "发送页数写入确认数据帧报文字节7";
CM_ SG_ 2500193895 D2P_WriteOK_Byte0_39 "发送页数写入确认数据帧报文字节0";
CM_ SG_ 2500193895 D2P_WriteOK_Byte1_39 "发送页数写入确认数据帧报文字节1";
CM_ SG_ 2500193895 D2P_WriteOK_Byte2_39 "发送页数写入确认数据帧报文字节2";
CM_ SG_ 2500193895 D2P_WriteOK_Byte3_39 "发送页数写入确认数据帧报文字节3";
CM_ SG_ 2500193895 D2P_WriteOK_Byte4_39 "发送页数写入确认数据帧报文字节4";
CM_ SG_ 2500193895 D2P_WriteOK_Byte5_39 "发送页数写入确认数据帧报文字节5";
CM_ SG_ 2500193895 D2P_WriteOK_Byte6_39 "发送页数写入确认数据帧报文字节6";
CM_ SG_ 2500193895 D2P_WriteOK_Byte7_39 "发送页数写入确认数据帧报文字节7";
CM_ SG_ 2500193896 D2P_WriteOK_Byte0_40 "发送页数写入确认数据帧报文字节0";
CM_ SG_ 2500193896 D2P_WriteOK_Byte1_40 "发送页数写入确认数据帧报文字节1";
CM_ SG_ 2500193896 D2P_WriteOK_Byte2_40 "发送页数写入确认数据帧报文字节2";
CM_ SG_ 2500193896 D2P_WriteOK_Byte3_40 "发送页数写入确认数据帧报文字节3";
CM_ SG_ 2500193896 D2P_WriteOK_Byte4_40 "发送页数写入确认数据帧报文字节4";
CM_ SG_ 2500193896 D2P_WriteOK_Byte5_40 "发送页数写入确认数据帧报文字节5";
CM_ SG_ 2500193896 D2P_WriteOK_Byte6_40 "发送页数写入确认数据帧报文字节6";
CM_ SG_ 2500193896 D2P_WriteOK_Byte7_40 "发送页数写入确认数据帧报文字节7";
CM_ SG_ 2500193897 D2P_WriteOK_Byte0_41 "发送页数写入确认数据帧报文字节0";
CM_ SG_ 2500193897 D2P_WriteOK_Byte1_41 "发送页数写入确认数据帧报文字节1";
CM_ SG_ 2500193897 D2P_WriteOK_Byte2_41 "发送页数写入确认数据帧报文字节2";
CM_ SG_ 2500193897 D2P_WriteOK_Byte3_41 "发送页数写入确认数据帧报文字节3";
CM_ SG_ 2500193897 D2P_WriteOK_Byte4_41 "发送页数写入确认数据帧报文字节4";
CM_ SG_ 2500193897 D2P_WriteOK_Byte5_41 "发送页数写入确认数据帧报文字节5";
CM_ SG_ 2500193897 D2P_WriteOK_Byte6_41 "发送页数写入确认数据帧报文字节6";
CM_ SG_ 2500193897 D2P_WriteOK_Byte7_41 "发送页数写入确认数据帧报文字节7";
CM_ SG_ 2500193898 D2P_WriteOK_Byte0_42 "发送页数写入确认数据帧报文字节0";
CM_ SG_ 2500193898 D2P_WriteOK_Byte1_42 "发送页数写入确认数据帧报文字节1";
CM_ SG_ 2500193898 D2P_WriteOK_Byte2_42 "发送页数写入确认数据帧报文字节2";
CM_ SG_ 2500193898 D2P_WriteOK_Byte3_42 "发送页数写入确认数据帧报文字节3";
CM_ SG_ 2500193898 D2P_WriteOK_Byte4_42 "发送页数写入确认数据帧报文字节4";
CM_ SG_ 2500193898 D2P_WriteOK_Byte5_42 "发送页数写入确认数据帧报文字节5";
CM_ SG_ 2500193898 D2P_WriteOK_Byte6_42 "发送页数写入确认数据帧报文字节6";
CM_ SG_ 2500193898 D2P_WriteOK_Byte7_42 "发送页数写入确认数据帧报文字节7";
CM_ SG_ 2500193899 D2P_WriteOK_Byte0_43 "发送页数写入确认数据帧报文字节0";
CM_ SG_ 2500193899 D2P_WriteOK_Byte1_43 "发送页数写入确认数据帧报文字节1";
CM_ SG_ 2500193899 D2P_WriteOK_Byte2_43 "发送页数写入确认数据帧报文字节2";
CM_ SG_ 2500193899 D2P_WriteOK_Byte3_43 "发送页数写入确认数据帧报文字节3";
CM_ SG_ 2500193899 D2P_WriteOK_Byte4_43 "发送页数写入确认数据帧报文字节4";
CM_ SG_ 2500193899 D2P_WriteOK_Byte5_43 "发送页数写入确认数据帧报文字节5";
CM_ SG_ 2500193899 D2P_WriteOK_Byte6_43 "发送页数写入确认数据帧报文字节6";
CM_ SG_ 2500193899 D2P_WriteOK_Byte7_43 "发送页数写入确认数据帧报文字节7";
CM_ SG_ 2500193900 D2P_WriteOK_Byte0_44 "发送页数写入确认数据帧报文字节0";
CM_ SG_ 2500193900 D2P_WriteOK_Byte1_44 "发送页数写入确认数据帧报文字节1";
CM_ SG_ 2500193900 D2P_WriteOK_Byte2_44 "发送页数写入确认数据帧报文字节2";
CM_ SG_ 2500193900 D2P_WriteOK_Byte3_44 "发送页数写入确认数据帧报文字节3";
CM_ SG_ 2500193900 D2P_WriteOK_Byte4_44 "发送页数写入确认数据帧报文字节4";
CM_ SG_ 2500193900 D2P_WriteOK_Byte5_44 "发送页数写入确认数据帧报文字节5";
CM_ SG_ 2500193900 D2P_WriteOK_Byte6_44 "发送页数写入确认数据帧报文字节6";
CM_ SG_ 2500193900 D2P_WriteOK_Byte7_44 "发送页数写入确认数据帧报文字节7";
CM_ SG_ 2500193901 D2P_WriteOK_Byte0_45 "发送页数写入确认数据帧报文字节0";
CM_ SG_ 2500193901 D2P_WriteOK_Byte1_45 "发送页数写入确认数据帧报文字节1";
CM_ SG_ 2500193901 D2P_WriteOK_Byte2_45 "发送页数写入确认数据帧报文字节2";
CM_ SG_ 2500193901 D2P_WriteOK_Byte3_45 "发送页数写入确认数据帧报文字节3";
CM_ SG_ 2500193901 D2P_WriteOK_Byte4_45 "发送页数写入确认数据帧报文字节4";
CM_ SG_ 2500193901 D2P_WriteOK_Byte5_45 "发送页数写入确认数据帧报文字节5";
CM_ SG_ 2500193901 D2P_WriteOK_Byte6_45 "发送页数写入确认数据帧报文字节6";
CM_ SG_ 2500193901 D2P_WriteOK_Byte7_45 "发送页数写入确认数据帧报文字节7";
CM_ SG_ 2500193902 D2P_WriteOK_Byte0_46 "发送页数写入确认数据帧报文字节0";
CM_ SG_ 2500193902 D2P_WriteOK_Byte1_46 "发送页数写入确认数据帧报文字节1";
CM_ SG_ 2500193902 D2P_WriteOK_Byte2_46 "发送页数写入确认数据帧报文字节2";
CM_ SG_ 2500193902 D2P_WriteOK_Byte3_46 "发送页数写入确认数据帧报文字节3";
CM_ SG_ 2500193902 D2P_WriteOK_Byte4_46 "发送页数写入确认数据帧报文字节4";
CM_ SG_ 2500193902 D2P_WriteOK_Byte5_46 "发送页数写入确认数据帧报文字节5";
CM_ SG_ 2500193902 D2P_WriteOK_Byte6_46 "发送页数写入确认数据帧报文字节6";
CM_ SG_ 2500193902 D2P_WriteOK_Byte7_46 "发送页数写入确认数据帧报文字节7";
CM_ SG_ 2500193903 D2P_WriteOK_Byte0_47 "发送页数写入确认数据帧报文字节0";
CM_ SG_ 2500193903 D2P_WriteOK_Byte1_47 "发送页数写入确认数据帧报文字节1";
CM_ SG_ 2500193903 D2P_WriteOK_Byte2_47 "发送页数写入确认数据帧报文字节2";
CM_ SG_ 2500193903 D2P_WriteOK_Byte3_47 "发送页数写入确认数据帧报文字节3";
CM_ SG_ 2500193903 D2P_WriteOK_Byte4_47 "发送页数写入确认数据帧报文字节4";
CM_ SG_ 2500193903 D2P_WriteOK_Byte5_47 "发送页数写入确认数据帧报文字节5";
CM_ SG_ 2500193903 D2P_WriteOK_Byte6_47 "发送页数写入确认数据帧报文字节6";
CM_ SG_ 2500193903 D2P_WriteOK_Byte7_47 "发送页数写入确认数据帧报文字节7";
CM_ SG_ 2500193904 D2P_WriteOK_Byte0_48 "发送页数写入确认数据帧报文字节0";
CM_ SG_ 2500193904 D2P_WriteOK_Byte1_48 "发送页数写入确认数据帧报文字节1";
CM_ SG_ 2500193904 D2P_WriteOK_Byte2_48 "发送页数写入确认数据帧报文字节2";
CM_ SG_ 2500193904 D2P_WriteOK_Byte3_48 "发送页数写入确认数据帧报文字节3";
CM_ SG_ 2500193904 D2P_WriteOK_Byte4_48 "发送页数写入确认数据帧报文字节4";
CM_ SG_ 2500193904 D2P_WriteOK_Byte5_48 "发送页数写入确认数据帧报文字节5";
CM_ SG_ 2500193904 D2P_WriteOK_Byte6_48 "发送页数写入确认数据帧报文字节6";
CM_ SG_ 2500193904 D2P_WriteOK_Byte7_48 "发送页数写入确认数据帧报文字节7";
CM_ SG_ 2500193905 D2P_WriteOK_Byte0_49 "发送页数写入确认数据帧报文字节0";
CM_ SG_ 2500193905 D2P_WriteOK_Byte1_49 "发送页数写入确认数据帧报文字节1";
CM_ SG_ 2500193905 D2P_WriteOK_Byte2_49 "发送页数写入确认数据帧报文字节2";
CM_ SG_ 2500193905 D2P_WriteOK_Byte3_49 "发送页数写入确认数据帧报文字节3";
CM_ SG_ 2500193905 D2P_WriteOK_Byte4_49 "发送页数写入确认数据帧报文字节4";
CM_ SG_ 2500193905 D2P_WriteOK_Byte5_49 "发送页数写入确认数据帧报文字节5";
CM_ SG_ 2500193905 D2P_WriteOK_Byte6_49 "发送页数写入确认数据帧报文字节6";
CM_ SG_ 2500193905 D2P_WriteOK_Byte7_49 "发送页数写入确认数据帧报文字节7";
CM_ SG_ 2500193906 D2P_WriteOK_Byte0_50 "发送页数写入确认数据帧报文字节0";
CM_ SG_ 2500193906 D2P_WriteOK_Byte1_50 "发送页数写入确认数据帧报文字节1";
CM_ SG_ 2500193906 D2P_WriteOK_Byte2_50 "发送页数写入确认数据帧报文字节2";
CM_ SG_ 2500193906 D2P_WriteOK_Byte3_50 "发送页数写入确认数据帧报文字节3";
CM_ SG_ 2500193906 D2P_WriteOK_Byte4_50 "发送页数写入确认数据帧报文字节4";
CM_ SG_ 2500193906 D2P_WriteOK_Byte5_50 "发送页数写入确认数据帧报文字节5";
CM_ SG_ 2500193906 D2P_WriteOK_Byte6_50 "发送页数写入确认数据帧报文字节6";
CM_ SG_ 2500193906 D2P_WriteOK_Byte7_50 "发送页数写入确认数据帧报文字节7";
CM_ SG_ 2500193907 D2P_WriteOK_Byte0_51 "发送页数写入确认数据帧报文字节0";
CM_ SG_ 2500193907 D2P_WriteOK_Byte1_51 "发送页数写入确认数据帧报文字节1";
CM_ SG_ 2500193907 D2P_WriteOK_Byte2_51 "发送页数写入确认数据帧报文字节2";
CM_ SG_ 2500193907 D2P_WriteOK_Byte3_51 "发送页数写入确认数据帧报文字节3";
CM_ SG_ 2500193907 D2P_WriteOK_Byte4_51 "发送页数写入确认数据帧报文字节4";
CM_ SG_ 2500193907 D2P_WriteOK_Byte5_51 "发送页数写入确认数据帧报文字节5";
CM_ SG_ 2500193907 D2P_WriteOK_Byte6_51 "发送页数写入确认数据帧报文字节6";
CM_ SG_ 2500193907 D2P_WriteOK_Byte7_51 "发送页数写入确认数据帧报文字节7";
CM_ SG_ 2500193908 D2P_WriteOK_Byte0_52 "发送页数写入确认数据帧报文字节0";
CM_ SG_ 2500193908 D2P_WriteOK_Byte1_52 "发送页数写入确认数据帧报文字节1";
CM_ SG_ 2500193908 D2P_WriteOK_Byte2_52 "发送页数写入确认数据帧报文字节2";
CM_ SG_ 2500193908 D2P_WriteOK_Byte3_52 "发送页数写入确认数据帧报文字节3";
CM_ SG_ 2500193908 D2P_WriteOK_Byte4_52 "发送页数写入确认数据帧报文字节4";
CM_ SG_ 2500193908 D2P_WriteOK_Byte5_52 "发送页数写入确认数据帧报文字节5";
CM_ SG_ 2500193908 D2P_WriteOK_Byte6_52 "发送页数写入确认数据帧报文字节6";
CM_ SG_ 2500193908 D2P_WriteOK_Byte7_52 "发送页数写入确认数据帧报文字节7";
CM_ SG_ 2500193909 D2P_WriteOK_Byte0_53 "发送页数写入确认数据帧报文字节0";
CM_ SG_ 2500193909 D2P_WriteOK_Byte1_53 "发送页数写入确认数据帧报文字节1";
CM_ SG_ 2500193909 D2P_WriteOK_Byte2_53 "发送页数写入确认数据帧报文字节2";
CM_ SG_ 2500193909 D2P_WriteOK_Byte3_53 "发送页数写入确认数据帧报文字节3";
CM_ SG_ 2500193909 D2P_WriteOK_Byte4_53 "发送页数写入确认数据帧报文字节4";
CM_ SG_ 2500193909 D2P_WriteOK_Byte5_53 "发送页数写入确认数据帧报文字节5";
CM_ SG_ 2500193909 D2P_WriteOK_Byte6_53 "发送页数写入确认数据帧报文字节6";
CM_ SG_ 2500193909 D2P_WriteOK_Byte7_53 "发送页数写入确认数据帧报文字节7";
CM_ SG_ 2500193910 D2P_WriteOK_Byte0_54 "发送页数写入确认数据帧报文字节0";
CM_ SG_ 2500193910 D2P_WriteOK_Byte1_54 "发送页数写入确认数据帧报文字节1";
CM_ SG_ 2500193910 D2P_WriteOK_Byte2_54 "发送页数写入确认数据帧报文字节2";
CM_ SG_ 2500193910 D2P_WriteOK_Byte3_54 "发送页数写入确认数据帧报文字节3";
CM_ SG_ 2500193910 D2P_WriteOK_Byte4_54 "发送页数写入确认数据帧报文字节4";
CM_ SG_ 2500193910 D2P_WriteOK_Byte5_54 "发送页数写入确认数据帧报文字节5";
CM_ SG_ 2500193910 D2P_WriteOK_Byte6_54 "发送页数写入确认数据帧报文字节6";
CM_ SG_ 2500193910 D2P_WriteOK_Byte7_54 "发送页数写入确认数据帧报文字节7";
CM_ SG_ 2500193911 D2P_WriteOK_Byte0_55 "发送页数写入确认数据帧报文字节0";
CM_ SG_ 2500193911 D2P_WriteOK_Byte1_55 "发送页数写入确认数据帧报文字节1";
CM_ SG_ 2500193911 D2P_WriteOK_Byte2_55 "发送页数写入确认数据帧报文字节2";
CM_ SG_ 2500193911 D2P_WriteOK_Byte3_55 "发送页数写入确认数据帧报文字节3";
CM_ SG_ 2500193911 D2P_WriteOK_Byte4_55 "发送页数写入确认数据帧报文字节4";
CM_ SG_ 2500193911 D2P_WriteOK_Byte5_55 "发送页数写入确认数据帧报文字节5";
CM_ SG_ 2500193911 D2P_WriteOK_Byte6_55 "发送页数写入确认数据帧报文字节6";
CM_ SG_ 2500193911 D2P_WriteOK_Byte7_55 "发送页数写入确认数据帧报文字节7";
CM_ SG_ 2500193912 D2P_WriteOK_Byte0_56 "发送页数写入确认数据帧报文字节0";
CM_ SG_ 2500193912 D2P_WriteOK_Byte1_56 "发送页数写入确认数据帧报文字节1";
CM_ SG_ 2500193912 D2P_WriteOK_Byte2_56 "发送页数写入确认数据帧报文字节2";
CM_ SG_ 2500193912 D2P_WriteOK_Byte3_56 "发送页数写入确认数据帧报文字节3";
CM_ SG_ 2500193912 D2P_WriteOK_Byte4_56 "发送页数写入确认数据帧报文字节4";
CM_ SG_ 2500193912 D2P_WriteOK_Byte5_56 "发送页数写入确认数据帧报文字节5";
CM_ SG_ 2500193912 D2P_WriteOK_Byte6_56 "发送页数写入确认数据帧报文字节6";
CM_ SG_ 2500193912 D2P_WriteOK_Byte7_56 "发送页数写入确认数据帧报文字节7";
CM_ SG_ 2500193913 D2P_WriteOK_Byte0_57 "发送页数写入确认数据帧报文字节0";
CM_ SG_ 2500193913 D2P_WriteOK_Byte1_57 "发送页数写入确认数据帧报文字节1";
CM_ SG_ 2500193913 D2P_WriteOK_Byte2_57 "发送页数写入确认数据帧报文字节2";
CM_ SG_ 2500193913 D2P_WriteOK_Byte3_57 "发送页数写入确认数据帧报文字节3";
CM_ SG_ 2500193913 D2P_WriteOK_Byte4_57 "发送页数写入确认数据帧报文字节4";
CM_ SG_ 2500193913 D2P_WriteOK_Byte5_57 "发送页数写入确认数据帧报文字节5";
CM_ SG_ 2500193913 D2P_WriteOK_Byte6_57 "发送页数写入确认数据帧报文字节6";
CM_ SG_ 2500193913 D2P_WriteOK_Byte7_57 "发送页数写入确认数据帧报文字节7";
CM_ SG_ 2500193914 D2P_WriteOK_Byte0_58 "发送页数写入确认数据帧报文字节0";
CM_ SG_ 2500193914 D2P_WriteOK_Byte1_58 "发送页数写入确认数据帧报文字节1";
CM_ SG_ 2500193914 D2P_WriteOK_Byte2_58 "发送页数写入确认数据帧报文字节2";
CM_ SG_ 2500193914 D2P_WriteOK_Byte3_58 "发送页数写入确认数据帧报文字节3";
CM_ SG_ 2500193914 D2P_WriteOK_Byte4_58 "发送页数写入确认数据帧报文字节4";
CM_ SG_ 2500193914 D2P_WriteOK_Byte5_58 "发送页数写入确认数据帧报文字节5";
CM_ SG_ 2500193914 D2P_WriteOK_Byte6_58 "发送页数写入确认数据帧报文字节6";
CM_ SG_ 2500193914 D2P_WriteOK_Byte7_58 "发送页数写入确认数据帧报文字节7";
CM_ SG_ 2500193915 D2P_WriteOK_Byte0_59 "发送页数写入确认数据帧报文字节0";
CM_ SG_ 2500193915 D2P_WriteOK_Byte1_59 "发送页数写入确认数据帧报文字节1";
CM_ SG_ 2500193915 D2P_WriteOK_Byte2_59 "发送页数写入确认数据帧报文字节2";
CM_ SG_ 2500193915 D2P_WriteOK_Byte3_59 "发送页数写入确认数据帧报文字节3";
CM_ SG_ 2500193915 D2P_WriteOK_Byte4_59 "发送页数写入确认数据帧报文字节4";
CM_ SG_ 2500193915 D2P_WriteOK_Byte5_59 "发送页数写入确认数据帧报文字节5";
CM_ SG_ 2500193915 D2P_WriteOK_Byte6_59 "发送页数写入确认数据帧报文字节6";
CM_ SG_ 2500193915 D2P_WriteOK_Byte7_59 "发送页数写入确认数据帧报文字节7";
CM_ SG_ 2500193916 D2P_WriteOK_Byte0_60 "发送页数写入确认数据帧报文字节0";
CM_ SG_ 2500193916 D2P_WriteOK_Byte1_60 "发送页数写入确认数据帧报文字节1";
CM_ SG_ 2500193916 D2P_WriteOK_Byte2_60 "发送页数写入确认数据帧报文字节2";
CM_ SG_ 2500193916 D2P_WriteOK_Byte3_60 "发送页数写入确认数据帧报文字节3";
CM_ SG_ 2500193916 D2P_WriteOK_Byte4_60 "发送页数写入确认数据帧报文字节4";
CM_ SG_ 2500193916 D2P_WriteOK_Byte5_60 "发送页数写入确认数据帧报文字节5";
CM_ SG_ 2500193916 D2P_WriteOK_Byte6_60 "发送页数写入确认数据帧报文字节6";
CM_ SG_ 2500193916 D2P_WriteOK_Byte7_60 "发送页数写入确认数据帧报文字节7";
CM_ SG_ 2500193917 D2P_WriteOK_Byte0_61 "发送页数写入确认数据帧报文字节0";
CM_ SG_ 2500193917 D2P_WriteOK_Byte1_61 "发送页数写入确认数据帧报文字节1";
CM_ SG_ 2500193917 D2P_WriteOK_Byte2_61 "发送页数写入确认数据帧报文字节2";
CM_ SG_ 2500193917 D2P_WriteOK_Byte3_61 "发送页数写入确认数据帧报文字节3";
CM_ SG_ 2500193917 D2P_WriteOK_Byte4_61 "发送页数写入确认数据帧报文字节4";
CM_ SG_ 2500193917 D2P_WriteOK_Byte5_61 "发送页数写入确认数据帧报文字节5";
CM_ SG_ 2500193917 D2P_WriteOK_Byte6_61 "发送页数写入确认数据帧报文字节6";
CM_ SG_ 2500193917 D2P_WriteOK_Byte7_61 "发送页数写入确认数据帧报文字节7";
CM_ SG_ 2500193918 D2P_WriteOK_Byte0_62 "发送页数写入确认数据帧报文字节0";
CM_ SG_ 2500193918 D2P_WriteOK_Byte1_62 "发送页数写入确认数据帧报文字节1";
CM_ SG_ 2500193918 D2P_WriteOK_Byte2_62 "发送页数写入确认数据帧报文字节2";
CM_ SG_ 2500193918 D2P_WriteOK_Byte3_62 "发送页数写入确认数据帧报文字节3";
CM_ SG_ 2500193918 D2P_WriteOK_Byte4_62 "发送页数写入确认数据帧报文字节4";
CM_ SG_ 2500193918 D2P_WriteOK_Byte5_62 "发送页数写入确认数据帧报文字节5";
CM_ SG_ 2500193918 D2P_WriteOK_Byte6_62 "发送页数写入确认数据帧报文字节6";
CM_ SG_ 2500193918 D2P_WriteOK_Byte7_62 "发送页数写入确认数据帧报文字节7";
CM_ SG_ 2500193919 D2P_WriteOK_Byte0_63 "发送页数写入确认数据帧报文字节0";
CM_ SG_ 2500193919 D2P_WriteOK_Byte1_63 "发送页数写入确认数据帧报文字节1";
CM_ SG_ 2500193919 D2P_WriteOK_Byte2_63 "发送页数写入确认数据帧报文字节2";
CM_ SG_ 2500193919 D2P_WriteOK_Byte3_63 "发送页数写入确认数据帧报文字节3";
CM_ SG_ 2500193919 D2P_WriteOK_Byte4_63 "发送页数写入确认数据帧报文字节4";
CM_ SG_ 2500193919 D2P_WriteOK_Byte5_63 "发送页数写入确认数据帧报文字节5";
CM_ SG_ 2500193919 D2P_WriteOK_Byte6_63 "发送页数写入确认数据帧报文字节6";
CM_ SG_ 2500193919 D2P_WriteOK_Byte7_63 "发送页数写入确认数据帧报文字节7";
CM_ SG_ 2332884801 D2M_SUMDATA1_CRC_01 "CRC校验";
CM_ SG_ 2332884801 D2M_SUMDATA1_DCDC_Life_01 "生命信号，0~15循环";
CM_ SG_ 2332884801 D2M_DCDC_RQ_Mode_Set_01 "预留";
CM_ SG_ 2332884801 D2M_DCDC_Work_State_01 "DCDC工作状态";
CM_ SG_ 2332884801 D2M_DCDC_AlarmSigl_State_01 "DCDC Alarm信号状态";
CM_ SG_ 2332884801 D2M_DCDC_LVPower_State_01 "DCDC低压供电电源状态";
CM_ SG_ 2332884801 D2M_DCDC_Enableline_State_01 "DCDC硬线使能信号状态(预留)";
CM_ SG_ 2332884801 D2M_Communication_State_01 "DCDC与MBMU通讯状态";
CM_ SG_ 2332884801 D2M_SUMDATA1_Reserved1_01 "预留1";
CM_ SG_ 2332884801 D2M_DCDC_PCBTemp_01 "DCDC 板温";
CM_ SG_ 2332884801 D2M_DCDC_MosTemp1_01 "DCDC 一级MOS温度";
CM_ SG_ 2332884801 D2M_DCDC_MosTemp2_01 "DCDC 二级MOS温度";
CM_ SG_ 2332884801 D2M_DCDC_TransformerTemp_01 "DCDC 变压器温度";
CM_ SG_ 2332884801 D2M_DCDC_Sleep_State_01 "DCDC休眠状态";
CM_ SG_ 2332884801 D2M_SUMDATA1_Reserved_01 "预留2";
CM_ SG_ 2332884802 D2M_SUMDATA1_CRC_02 "CRC校验";
CM_ SG_ 2332884802 D2M_SUMDATA1_DCDC_Life_02 "生命信号，0~15循环";
CM_ SG_ 2332884802 D2M_DCDC_RQ_Mode_Set_02 "预留";
CM_ SG_ 2332884802 D2M_DCDC_Work_State_02 "DCDC工作状态";
CM_ SG_ 2332884802 D2M_DCDC_AlarmSigl_State_02 "DCDC Alarm信号状态";
CM_ SG_ 2332884802 D2M_DCDC_LVPower_State_02 "DCDC低压供电电源状态";
CM_ SG_ 2332884802 D2M_DCDC_Enableline_State_02 "DCDC硬线使能信号状态(预留)";
CM_ SG_ 2332884802 D2M_Communication_State_02 "DCDC与MBMU通讯状态";
CM_ SG_ 2332884802 D2M_SUMDATA1_Reserved1_02 "预留1";
CM_ SG_ 2332884802 D2M_DCDC_PCBTemp_02 "DCDC 板温";
CM_ SG_ 2332884802 D2M_DCDC_MosTemp1_02 "DCDC 一级MOS温度";
CM_ SG_ 2332884802 D2M_DCDC_MosTemp2_02 "DCDC 二级MOS温度";
CM_ SG_ 2332884802 D2M_DCDC_TransformerTemp_02 "DCDC 变压器温度";
CM_ SG_ 2332884802 D2M_DCDC_Sleep_State_02 "DCDC休眠状态";
CM_ SG_ 2332884802 D2M_SUMDATA1_Reserved_02 "预留2";
CM_ SG_ 2332884803 D2M_SUMDATA1_CRC_03 "CRC校验";
CM_ SG_ 2332884803 D2M_SUMDATA1_DCDC_Life_03 "生命信号，0~15循环";
CM_ SG_ 2332884803 D2M_DCDC_RQ_Mode_Set_03 "预留";
CM_ SG_ 2332884803 D2M_DCDC_Work_State_03 "DCDC工作状态";
CM_ SG_ 2332884803 D2M_DCDC_AlarmSigl_State_03 "DCDC Alarm信号状态";
CM_ SG_ 2332884803 D2M_DCDC_LVPower_State_03 "DCDC低压供电电源状态";
CM_ SG_ 2332884803 D2M_DCDC_Enableline_State_03 "DCDC硬线使能信号状态(预留)";
CM_ SG_ 2332884803 D2M_Communication_State_03 "DCDC与MBMU通讯状态";
CM_ SG_ 2332884803 D2M_SUMDATA1_Reserved1_03 "预留1";
CM_ SG_ 2332884803 D2M_DCDC_PCBTemp_03 "DCDC 板温";
CM_ SG_ 2332884803 D2M_DCDC_MosTemp1_03 "DCDC 一级MOS温度";
CM_ SG_ 2332884803 D2M_DCDC_MosTemp2_03 "DCDC 二级MOS温度";
CM_ SG_ 2332884803 D2M_DCDC_TransformerTemp_03 "DCDC 变压器温度";
CM_ SG_ 2332884803 D2M_DCDC_Sleep_State_03 "DCDC休眠状态";
CM_ SG_ 2332884803 D2M_SUMDATA1_Reserved_03 "预留2";
CM_ SG_ 2332884804 D2M_SUMDATA1_CRC_04 "CRC校验";
CM_ SG_ 2332884804 D2M_SUMDATA1_DCDC_Life_04 "生命信号，0~15循环";
CM_ SG_ 2332884804 D2M_DCDC_RQ_Mode_Set_04 "预留";
CM_ SG_ 2332884804 D2M_DCDC_Work_State_04 "DCDC工作状态";
CM_ SG_ 2332884804 D2M_DCDC_AlarmSigl_State_04 "DCDC Alarm信号状态";
CM_ SG_ 2332884804 D2M_DCDC_LVPower_State_04 "DCDC低压供电电源状态";
CM_ SG_ 2332884804 D2M_DCDC_Enableline_State_04 "DCDC硬线使能信号状态(预留)";
CM_ SG_ 2332884804 D2M_Communication_State_04 "DCDC与MBMU通讯状态";
CM_ SG_ 2332884804 D2M_SUMDATA1_Reserved1_04 "预留1";
CM_ SG_ 2332884804 D2M_DCDC_PCBTemp_04 "DCDC 板温";
CM_ SG_ 2332884804 D2M_DCDC_MosTemp1_04 "DCDC 一级MOS温度";
CM_ SG_ 2332884804 D2M_DCDC_MosTemp2_04 "DCDC 二级MOS温度";
CM_ SG_ 2332884804 D2M_DCDC_TransformerTemp_04 "DCDC 变压器温度";
CM_ SG_ 2332884804 D2M_DCDC_Sleep_State_04 "DCDC休眠状态";
CM_ SG_ 2332884804 D2M_SUMDATA1_Reserved_04 "预留2";
CM_ SG_ 2332884805 D2M_SUMDATA1_CRC_05 "CRC校验";
CM_ SG_ 2332884805 D2M_SUMDATA1_DCDC_Life_05 "生命信号，0~15循环";
CM_ SG_ 2332884805 D2M_DCDC_RQ_Mode_Set_05 "预留";
CM_ SG_ 2332884805 D2M_DCDC_Work_State_05 "DCDC工作状态";
CM_ SG_ 2332884805 D2M_DCDC_AlarmSigl_State_05 "DCDC Alarm信号状态";
CM_ SG_ 2332884805 D2M_DCDC_LVPower_State_05 "DCDC低压供电电源状态";
CM_ SG_ 2332884805 D2M_DCDC_Enableline_State_05 "DCDC硬线使能信号状态(预留)";
CM_ SG_ 2332884805 D2M_Communication_State_05 "DCDC与MBMU通讯状态";
CM_ SG_ 2332884805 D2M_SUMDATA1_Reserved1_05 "预留1";
CM_ SG_ 2332884805 D2M_DCDC_PCBTemp_05 "DCDC 板温";
CM_ SG_ 2332884805 D2M_DCDC_MosTemp1_05 "DCDC 一级MOS温度";
CM_ SG_ 2332884805 D2M_DCDC_MosTemp2_05 "DCDC 二级MOS温度";
CM_ SG_ 2332884805 D2M_DCDC_TransformerTemp_05 "DCDC 变压器温度";
CM_ SG_ 2332884805 D2M_DCDC_Sleep_State_05 "DCDC休眠状态";
CM_ SG_ 2332884805 D2M_SUMDATA1_Reserved_05 "预留2";
CM_ SG_ 2332884806 D2M_SUMDATA1_CRC_06 "CRC校验";
CM_ SG_ 2332884806 D2M_SUMDATA1_DCDC_Life_06 "生命信号，0~15循环";
CM_ SG_ 2332884806 D2M_DCDC_RQ_Mode_Set_06 "预留";
CM_ SG_ 2332884806 D2M_DCDC_Work_State_06 "DCDC工作状态";
CM_ SG_ 2332884806 D2M_DCDC_AlarmSigl_State_06 "DCDC Alarm信号状态";
CM_ SG_ 2332884806 D2M_DCDC_LVPower_State_06 "DCDC低压供电电源状态";
CM_ SG_ 2332884806 D2M_DCDC_Enableline_State_06 "DCDC硬线使能信号状态(预留)";
CM_ SG_ 2332884806 D2M_Communication_State_06 "DCDC与MBMU通讯状态";
CM_ SG_ 2332884806 D2M_SUMDATA1_Reserved1_06 "预留1";
CM_ SG_ 2332884806 D2M_DCDC_PCBTemp_06 "DCDC 板温";
CM_ SG_ 2332884806 D2M_DCDC_MosTemp1_06 "DCDC 一级MOS温度";
CM_ SG_ 2332884806 D2M_DCDC_MosTemp2_06 "DCDC 二级MOS温度";
CM_ SG_ 2332884806 D2M_DCDC_TransformerTemp_06 "DCDC 变压器温度";
CM_ SG_ 2332884806 D2M_DCDC_Sleep_State_06 "DCDC休眠状态";
CM_ SG_ 2332884806 D2M_SUMDATA1_Reserved_06 "预留2";
CM_ SG_ 2332884807 D2M_SUMDATA1_CRC_07 "CRC校验";
CM_ SG_ 2332884807 D2M_SUMDATA1_DCDC_Life_07 "生命信号，0~15循环";
CM_ SG_ 2332884807 D2M_DCDC_RQ_Mode_Set_07 "预留";
CM_ SG_ 2332884807 D2M_DCDC_Work_State_07 "DCDC工作状态";
CM_ SG_ 2332884807 D2M_DCDC_AlarmSigl_State_07 "DCDC Alarm信号状态";
CM_ SG_ 2332884807 D2M_DCDC_LVPower_State_07 "DCDC低压供电电源状态";
CM_ SG_ 2332884807 D2M_DCDC_Enableline_State_07 "DCDC硬线使能信号状态(预留)";
CM_ SG_ 2332884807 D2M_Communication_State_07 "DCDC与MBMU通讯状态";
CM_ SG_ 2332884807 D2M_SUMDATA1_Reserved1_07 "预留1";
CM_ SG_ 2332884807 D2M_DCDC_PCBTemp_07 "DCDC 板温";
CM_ SG_ 2332884807 D2M_DCDC_MosTemp1_07 "DCDC 一级MOS温度";
CM_ SG_ 2332884807 D2M_DCDC_MosTemp2_07 "DCDC 二级MOS温度";
CM_ SG_ 2332884807 D2M_DCDC_TransformerTemp_07 "DCDC 变压器温度";
CM_ SG_ 2332884807 D2M_DCDC_Sleep_State_07 "DCDC休眠状态";
CM_ SG_ 2332884807 D2M_SUMDATA1_Reserved_07 "预留2";
CM_ SG_ 2332884808 D2M_SUMDATA1_CRC_08 "CRC校验";
CM_ SG_ 2332884808 D2M_SUMDATA1_DCDC_Life_08 "生命信号，0~15循环";
CM_ SG_ 2332884808 D2M_DCDC_RQ_Mode_Set_08 "预留";
CM_ SG_ 2332884808 D2M_DCDC_Work_State_08 "DCDC工作状态";
CM_ SG_ 2332884808 D2M_DCDC_AlarmSigl_State_08 "DCDC Alarm信号状态";
CM_ SG_ 2332884808 D2M_DCDC_LVPower_State_08 "DCDC低压供电电源状态";
CM_ SG_ 2332884808 D2M_DCDC_Enableline_State_08 "DCDC硬线使能信号状态(预留)";
CM_ SG_ 2332884808 D2M_Communication_State_08 "DCDC与MBMU通讯状态";
CM_ SG_ 2332884808 D2M_SUMDATA1_Reserved1_08 "预留1";
CM_ SG_ 2332884808 D2M_DCDC_PCBTemp_08 "DCDC 板温";
CM_ SG_ 2332884808 D2M_DCDC_MosTemp1_08 "DCDC 一级MOS温度";
CM_ SG_ 2332884808 D2M_DCDC_MosTemp2_08 "DCDC 二级MOS温度";
CM_ SG_ 2332884808 D2M_DCDC_TransformerTemp_08 "DCDC 变压器温度";
CM_ SG_ 2332884808 D2M_DCDC_Sleep_State_08 "DCDC休眠状态";
CM_ SG_ 2332884808 D2M_SUMDATA1_Reserved_08 "预留2";
CM_ SG_ 2332884809 D2M_SUMDATA1_CRC_09 "CRC校验";
CM_ SG_ 2332884809 D2M_SUMDATA1_DCDC_Life_09 "生命信号，0~15循环";
CM_ SG_ 2332884809 D2M_DCDC_RQ_Mode_Set_09 "预留";
CM_ SG_ 2332884809 D2M_DCDC_Work_State_09 "DCDC工作状态";
CM_ SG_ 2332884809 D2M_DCDC_AlarmSigl_State_09 "DCDC Alarm信号状态";
CM_ SG_ 2332884809 D2M_DCDC_LVPower_State_09 "DCDC低压供电电源状态";
CM_ SG_ 2332884809 D2M_DCDC_Enableline_State_09 "DCDC硬线使能信号状态(预留)";
CM_ SG_ 2332884809 D2M_Communication_State_09 "DCDC与MBMU通讯状态";
CM_ SG_ 2332884809 D2M_SUMDATA1_Reserved1_09 "预留1";
CM_ SG_ 2332884809 D2M_DCDC_PCBTemp_09 "DCDC 板温";
CM_ SG_ 2332884809 D2M_DCDC_MosTemp1_09 "DCDC 一级MOS温度";
CM_ SG_ 2332884809 D2M_DCDC_MosTemp2_09 "DCDC 二级MOS温度";
CM_ SG_ 2332884809 D2M_DCDC_TransformerTemp_09 "DCDC 变压器温度";
CM_ SG_ 2332884809 D2M_DCDC_Sleep_State_09 "DCDC休眠状态";
CM_ SG_ 2332884809 D2M_SUMDATA1_Reserved_09 "预留2";
CM_ SG_ 2332884810 D2M_SUMDATA1_CRC_10 "CRC校验";
CM_ SG_ 2332884810 D2M_SUMDATA1_DCDC_Life_10 "生命信号，0~15循环";
CM_ SG_ 2332884810 D2M_DCDC_RQ_Mode_Set_10 "预留";
CM_ SG_ 2332884810 D2M_DCDC_Work_State_10 "DCDC工作状态";
CM_ SG_ 2332884810 D2M_DCDC_AlarmSigl_State_10 "DCDC Alarm信号状态";
CM_ SG_ 2332884810 D2M_DCDC_LVPower_State_10 "DCDC低压供电电源状态";
CM_ SG_ 2332884810 D2M_DCDC_Enableline_State_10 "DCDC硬线使能信号状态(预留)";
CM_ SG_ 2332884810 D2M_Communication_State_10 "DCDC与MBMU通讯状态";
CM_ SG_ 2332884810 D2M_SUMDATA1_Reserved1_10 "预留1";
CM_ SG_ 2332884810 D2M_DCDC_PCBTemp_10 "DCDC 板温";
CM_ SG_ 2332884810 D2M_DCDC_MosTemp1_10 "DCDC 一级MOS温度";
CM_ SG_ 2332884810 D2M_DCDC_MosTemp2_10 "DCDC 二级MOS温度";
CM_ SG_ 2332884810 D2M_DCDC_TransformerTemp_10 "DCDC 变压器温度";
CM_ SG_ 2332884810 D2M_DCDC_Sleep_State_10 "DCDC休眠状态";
CM_ SG_ 2332884810 D2M_SUMDATA1_Reserved_10 "预留2";
CM_ SG_ 2332884811 D2M_SUMDATA1_CRC_11 "CRC校验";
CM_ SG_ 2332884811 D2M_SUMDATA1_DCDC_Life_11 "生命信号，0~15循环";
CM_ SG_ 2332884811 D2M_DCDC_RQ_Mode_Set_11 "预留";
CM_ SG_ 2332884811 D2M_DCDC_Work_State_11 "DCDC工作状态";
CM_ SG_ 2332884811 D2M_DCDC_AlarmSigl_State_11 "DCDC Alarm信号状态";
CM_ SG_ 2332884811 D2M_DCDC_LVPower_State_11 "DCDC低压供电电源状态";
CM_ SG_ 2332884811 D2M_DCDC_Enableline_State_11 "DCDC硬线使能信号状态(预留)";
CM_ SG_ 2332884811 D2M_Communication_State_11 "DCDC与MBMU通讯状态";
CM_ SG_ 2332884811 D2M_SUMDATA1_Reserved1_11 "预留1";
CM_ SG_ 2332884811 D2M_DCDC_PCBTemp_11 "DCDC 板温";
CM_ SG_ 2332884811 D2M_DCDC_MosTemp1_11 "DCDC 一级MOS温度";
CM_ SG_ 2332884811 D2M_DCDC_MosTemp2_11 "DCDC 二级MOS温度";
CM_ SG_ 2332884811 D2M_DCDC_TransformerTemp_11 "DCDC 变压器温度";
CM_ SG_ 2332884811 D2M_DCDC_Sleep_State_11 "DCDC休眠状态";
CM_ SG_ 2332884811 D2M_SUMDATA1_Reserved_11 "预留2";
CM_ SG_ 2332884812 D2M_SUMDATA1_CRC_12 "CRC校验";
CM_ SG_ 2332884812 D2M_SUMDATA1_DCDC_Life_12 "生命信号，0~15循环";
CM_ SG_ 2332884812 D2M_DCDC_RQ_Mode_Set_12 "预留";
CM_ SG_ 2332884812 D2M_DCDC_Work_State_12 "DCDC工作状态";
CM_ SG_ 2332884812 D2M_DCDC_AlarmSigl_State_12 "DCDC Alarm信号状态";
CM_ SG_ 2332884812 D2M_DCDC_LVPower_State_12 "DCDC低压供电电源状态";
CM_ SG_ 2332884812 D2M_DCDC_Enableline_State_12 "DCDC硬线使能信号状态(预留)";
CM_ SG_ 2332884812 D2M_Communication_State_12 "DCDC与MBMU通讯状态";
CM_ SG_ 2332884812 D2M_SUMDATA1_Reserved1_12 "预留1";
CM_ SG_ 2332884812 D2M_DCDC_PCBTemp_12 "DCDC 板温";
CM_ SG_ 2332884812 D2M_DCDC_MosTemp1_12 "DCDC 一级MOS温度";
CM_ SG_ 2332884812 D2M_DCDC_MosTemp2_12 "DCDC 二级MOS温度";
CM_ SG_ 2332884812 D2M_DCDC_TransformerTemp_12 "DCDC 变压器温度";
CM_ SG_ 2332884812 D2M_DCDC_Sleep_State_12 "DCDC休眠状态";
CM_ SG_ 2332884812 D2M_SUMDATA1_Reserved_12 "预留2";
CM_ SG_ 2332884813 D2M_SUMDATA1_CRC_13 "CRC校验";
CM_ SG_ 2332884813 D2M_SUMDATA1_DCDC_Life_13 "生命信号，0~15循环";
CM_ SG_ 2332884813 D2M_DCDC_RQ_Mode_Set_13 "预留";
CM_ SG_ 2332884813 D2M_DCDC_Work_State_13 "DCDC工作状态";
CM_ SG_ 2332884813 D2M_DCDC_AlarmSigl_State_13 "DCDC Alarm信号状态";
CM_ SG_ 2332884813 D2M_DCDC_LVPower_State_13 "DCDC低压供电电源状态";
CM_ SG_ 2332884813 D2M_DCDC_Enableline_State_13 "DCDC硬线使能信号状态(预留)";
CM_ SG_ 2332884813 D2M_Communication_State_13 "DCDC与MBMU通讯状态";
CM_ SG_ 2332884813 D2M_SUMDATA1_Reserved1_13 "预留1";
CM_ SG_ 2332884813 D2M_DCDC_PCBTemp_13 "DCDC 板温";
CM_ SG_ 2332884813 D2M_DCDC_MosTemp1_13 "DCDC 一级MOS温度";
CM_ SG_ 2332884813 D2M_DCDC_MosTemp2_13 "DCDC 二级MOS温度";
CM_ SG_ 2332884813 D2M_DCDC_TransformerTemp_13 "DCDC 变压器温度";
CM_ SG_ 2332884813 D2M_DCDC_Sleep_State_13 "DCDC休眠状态";
CM_ SG_ 2332884813 D2M_SUMDATA1_Reserved_13 "预留2";
CM_ SG_ 2332884814 D2M_SUMDATA1_CRC_14 "CRC校验";
CM_ SG_ 2332884814 D2M_SUMDATA1_DCDC_Life_14 "生命信号，0~15循环";
CM_ SG_ 2332884814 D2M_DCDC_RQ_Mode_Set_14 "预留";
CM_ SG_ 2332884814 D2M_DCDC_Work_State_14 "DCDC工作状态";
CM_ SG_ 2332884814 D2M_DCDC_AlarmSigl_State_14 "DCDC Alarm信号状态";
CM_ SG_ 2332884814 D2M_DCDC_LVPower_State_14 "DCDC低压供电电源状态";
CM_ SG_ 2332884814 D2M_DCDC_Enableline_State_14 "DCDC硬线使能信号状态(预留)";
CM_ SG_ 2332884814 D2M_Communication_State_14 "DCDC与MBMU通讯状态";
CM_ SG_ 2332884814 D2M_SUMDATA1_Reserved1_14 "预留1";
CM_ SG_ 2332884814 D2M_DCDC_PCBTemp_14 "DCDC 板温";
CM_ SG_ 2332884814 D2M_DCDC_MosTemp1_14 "DCDC 一级MOS温度";
CM_ SG_ 2332884814 D2M_DCDC_MosTemp2_14 "DCDC 二级MOS温度";
CM_ SG_ 2332884814 D2M_DCDC_TransformerTemp_14 "DCDC 变压器温度";
CM_ SG_ 2332884814 D2M_DCDC_Sleep_State_14 "DCDC休眠状态";
CM_ SG_ 2332884814 D2M_SUMDATA1_Reserved_14 "预留2";
CM_ SG_ 2332884815 D2M_SUMDATA1_CRC_15 "CRC校验";
CM_ SG_ 2332884815 D2M_SUMDATA1_DCDC_Life_15 "生命信号，0~15循环";
CM_ SG_ 2332884815 D2M_DCDC_RQ_Mode_Set_15 "预留";
CM_ SG_ 2332884815 D2M_DCDC_Work_State_15 "DCDC工作状态";
CM_ SG_ 2332884815 D2M_DCDC_AlarmSigl_State_15 "DCDC Alarm信号状态";
CM_ SG_ 2332884815 D2M_DCDC_LVPower_State_15 "DCDC低压供电电源状态";
CM_ SG_ 2332884815 D2M_DCDC_Enableline_State_15 "DCDC硬线使能信号状态(预留)";
CM_ SG_ 2332884815 D2M_Communication_State_15 "DCDC与MBMU通讯状态";
CM_ SG_ 2332884815 D2M_SUMDATA1_Reserved1_15 "预留1";
CM_ SG_ 2332884815 D2M_DCDC_PCBTemp_15 "DCDC 板温";
CM_ SG_ 2332884815 D2M_DCDC_MosTemp1_15 "DCDC 一级MOS温度";
CM_ SG_ 2332884815 D2M_DCDC_MosTemp2_15 "DCDC 二级MOS温度";
CM_ SG_ 2332884815 D2M_DCDC_TransformerTemp_15 "DCDC 变压器温度";
CM_ SG_ 2332884815 D2M_DCDC_Sleep_State_15 "DCDC休眠状态";
CM_ SG_ 2332884815 D2M_SUMDATA1_Reserved_15 "预留2";
CM_ SG_ 2332884816 D2M_SUMDATA1_CRC_16 "CRC校验";
CM_ SG_ 2332884816 D2M_SUMDATA1_DCDC_Life_16 "生命信号，0~15循环";
CM_ SG_ 2332884816 D2M_DCDC_RQ_Mode_Set_16 "预留";
CM_ SG_ 2332884816 D2M_DCDC_Work_State_16 "DCDC工作状态";
CM_ SG_ 2332884816 D2M_DCDC_AlarmSigl_State_16 "DCDC Alarm信号状态";
CM_ SG_ 2332884816 D2M_DCDC_LVPower_State_16 "DCDC低压供电电源状态";
CM_ SG_ 2332884816 D2M_DCDC_Enableline_State_16 "DCDC硬线使能信号状态(预留)";
CM_ SG_ 2332884816 D2M_Communication_State_16 "DCDC与MBMU通讯状态";
CM_ SG_ 2332884816 D2M_SUMDATA1_Reserved1_16 "预留1";
CM_ SG_ 2332884816 D2M_DCDC_PCBTemp_16 "DCDC 板温";
CM_ SG_ 2332884816 D2M_DCDC_MosTemp1_16 "DCDC 一级MOS温度";
CM_ SG_ 2332884816 D2M_DCDC_MosTemp2_16 "DCDC 二级MOS温度";
CM_ SG_ 2332884816 D2M_DCDC_TransformerTemp_16 "DCDC 变压器温度";
CM_ SG_ 2332884816 D2M_DCDC_Sleep_State_16 "DCDC休眠状态";
CM_ SG_ 2332884816 D2M_SUMDATA1_Reserved_16 "预留2";
CM_ SG_ 2332884817 D2M_SUMDATA1_CRC_17 "CRC校验";
CM_ SG_ 2332884817 D2M_SUMDATA1_DCDC_Life_17 "生命信号，0~15循环";
CM_ SG_ 2332884817 D2M_DCDC_RQ_Mode_Set_17 "预留";
CM_ SG_ 2332884817 D2M_DCDC_Work_State_17 "DCDC工作状态";
CM_ SG_ 2332884817 D2M_DCDC_AlarmSigl_State_17 "DCDC Alarm信号状态";
CM_ SG_ 2332884817 D2M_DCDC_LVPower_State_17 "DCDC低压供电电源状态";
CM_ SG_ 2332884817 D2M_DCDC_Enableline_State_17 "DCDC硬线使能信号状态(预留)";
CM_ SG_ 2332884817 D2M_Communication_State_17 "DCDC与MBMU通讯状态";
CM_ SG_ 2332884817 D2M_SUMDATA1_Reserved1_17 "预留1";
CM_ SG_ 2332884817 D2M_DCDC_PCBTemp_17 "DCDC 板温";
CM_ SG_ 2332884817 D2M_DCDC_MosTemp1_17 "DCDC 一级MOS温度";
CM_ SG_ 2332884817 D2M_DCDC_MosTemp2_17 "DCDC 二级MOS温度";
CM_ SG_ 2332884817 D2M_DCDC_TransformerTemp_17 "DCDC 变压器温度";
CM_ SG_ 2332884817 D2M_DCDC_Sleep_State_17 "DCDC休眠状态";
CM_ SG_ 2332884817 D2M_SUMDATA1_Reserved_17 "预留2";
CM_ SG_ 2332884818 D2M_SUMDATA1_CRC_18 "CRC校验";
CM_ SG_ 2332884818 D2M_SUMDATA1_DCDC_Life_18 "生命信号，0~15循环";
CM_ SG_ 2332884818 D2M_DCDC_RQ_Mode_Set_18 "预留";
CM_ SG_ 2332884818 D2M_DCDC_Work_State_18 "DCDC工作状态";
CM_ SG_ 2332884818 D2M_DCDC_AlarmSigl_State_18 "DCDC Alarm信号状态";
CM_ SG_ 2332884818 D2M_DCDC_LVPower_State_18 "DCDC低压供电电源状态";
CM_ SG_ 2332884818 D2M_DCDC_Enableline_State_18 "DCDC硬线使能信号状态(预留)";
CM_ SG_ 2332884818 D2M_Communication_State_18 "DCDC与MBMU通讯状态";
CM_ SG_ 2332884818 D2M_SUMDATA1_Reserved1_18 "预留1";
CM_ SG_ 2332884818 D2M_DCDC_PCBTemp_18 "DCDC 板温";
CM_ SG_ 2332884818 D2M_DCDC_MosTemp1_18 "DCDC 一级MOS温度";
CM_ SG_ 2332884818 D2M_DCDC_MosTemp2_18 "DCDC 二级MOS温度";
CM_ SG_ 2332884818 D2M_DCDC_TransformerTemp_18 "DCDC 变压器温度";
CM_ SG_ 2332884818 D2M_DCDC_Sleep_State_18 "DCDC休眠状态";
CM_ SG_ 2332884818 D2M_SUMDATA1_Reserved_18 "预留2";
CM_ SG_ 2332884819 D2M_SUMDATA1_CRC_19 "CRC校验";
CM_ SG_ 2332884819 D2M_SUMDATA1_DCDC_Life_19 "生命信号，0~15循环";
CM_ SG_ 2332884819 D2M_DCDC_RQ_Mode_Set_19 "预留";
CM_ SG_ 2332884819 D2M_DCDC_Work_State_19 "DCDC工作状态";
CM_ SG_ 2332884819 D2M_DCDC_AlarmSigl_State_19 "DCDC Alarm信号状态";
CM_ SG_ 2332884819 D2M_DCDC_LVPower_State_19 "DCDC低压供电电源状态";
CM_ SG_ 2332884819 D2M_DCDC_Enableline_State_19 "DCDC硬线使能信号状态(预留)";
CM_ SG_ 2332884819 D2M_Communication_State_19 "DCDC与MBMU通讯状态";
CM_ SG_ 2332884819 D2M_SUMDATA1_Reserved1_19 "预留1";
CM_ SG_ 2332884819 D2M_DCDC_PCBTemp_19 "DCDC 板温";
CM_ SG_ 2332884819 D2M_DCDC_MosTemp1_19 "DCDC 一级MOS温度";
CM_ SG_ 2332884819 D2M_DCDC_MosTemp2_19 "DCDC 二级MOS温度";
CM_ SG_ 2332884819 D2M_DCDC_TransformerTemp_19 "DCDC 变压器温度";
CM_ SG_ 2332884819 D2M_DCDC_Sleep_State_19 "DCDC休眠状态";
CM_ SG_ 2332884819 D2M_SUMDATA1_Reserved_19 "预留2";
CM_ SG_ 2332884820 D2M_SUMDATA1_CRC_20 "CRC校验";
CM_ SG_ 2332884820 D2M_SUMDATA1_DCDC_Life_20 "生命信号，0~15循环";
CM_ SG_ 2332884820 D2M_DCDC_RQ_Mode_Set_20 "预留";
CM_ SG_ 2332884820 D2M_DCDC_Work_State_20 "DCDC工作状态";
CM_ SG_ 2332884820 D2M_DCDC_AlarmSigl_State_20 "DCDC Alarm信号状态";
CM_ SG_ 2332884820 D2M_DCDC_LVPower_State_20 "DCDC低压供电电源状态";
CM_ SG_ 2332884820 D2M_DCDC_Enableline_State_20 "DCDC硬线使能信号状态(预留)";
CM_ SG_ 2332884820 D2M_Communication_State_20 "DCDC与MBMU通讯状态";
CM_ SG_ 2332884820 D2M_SUMDATA1_Reserved1_20 "预留1";
CM_ SG_ 2332884820 D2M_DCDC_PCBTemp_20 "DCDC 板温";
CM_ SG_ 2332884820 D2M_DCDC_MosTemp1_20 "DCDC 一级MOS温度";
CM_ SG_ 2332884820 D2M_DCDC_MosTemp2_20 "DCDC 二级MOS温度";
CM_ SG_ 2332884820 D2M_DCDC_TransformerTemp_20 "DCDC 变压器温度";
CM_ SG_ 2332884820 D2M_DCDC_Sleep_State_20 "DCDC休眠状态";
CM_ SG_ 2332884820 D2M_SUMDATA1_Reserved_20 "预留2";
CM_ SG_ 2332884821 D2M_SUMDATA1_CRC_21 "CRC校验";
CM_ SG_ 2332884821 D2M_SUMDATA1_DCDC_Life_21 "生命信号，0~15循环";
CM_ SG_ 2332884821 D2M_DCDC_RQ_Mode_Set_21 "预留";
CM_ SG_ 2332884821 D2M_DCDC_Work_State_21 "DCDC工作状态";
CM_ SG_ 2332884821 D2M_DCDC_AlarmSigl_State_21 "DCDC Alarm信号状态";
CM_ SG_ 2332884821 D2M_DCDC_LVPower_State_21 "DCDC低压供电电源状态";
CM_ SG_ 2332884821 D2M_DCDC_Enableline_State_21 "DCDC硬线使能信号状态(预留)";
CM_ SG_ 2332884821 D2M_Communication_State_21 "DCDC与MBMU通讯状态";
CM_ SG_ 2332884821 D2M_SUMDATA1_Reserved1_21 "预留1";
CM_ SG_ 2332884821 D2M_DCDC_PCBTemp_21 "DCDC 板温";
CM_ SG_ 2332884821 D2M_DCDC_MosTemp1_21 "DCDC 一级MOS温度";
CM_ SG_ 2332884821 D2M_DCDC_MosTemp2_21 "DCDC 二级MOS温度";
CM_ SG_ 2332884821 D2M_DCDC_TransformerTemp_21 "DCDC 变压器温度";
CM_ SG_ 2332884821 D2M_DCDC_Sleep_State_21 "DCDC休眠状态";
CM_ SG_ 2332884821 D2M_SUMDATA1_Reserved_21 "预留2";
CM_ SG_ 2332884822 D2M_SUMDATA1_CRC_22 "CRC校验";
CM_ SG_ 2332884822 D2M_SUMDATA1_DCDC_Life_22 "生命信号，0~15循环";
CM_ SG_ 2332884822 D2M_DCDC_RQ_Mode_Set_22 "预留";
CM_ SG_ 2332884822 D2M_DCDC_Work_State_22 "DCDC工作状态";
CM_ SG_ 2332884822 D2M_DCDC_AlarmSigl_State_22 "DCDC Alarm信号状态";
CM_ SG_ 2332884822 D2M_DCDC_LVPower_State_22 "DCDC低压供电电源状态";
CM_ SG_ 2332884822 D2M_DCDC_Enableline_State_22 "DCDC硬线使能信号状态(预留)";
CM_ SG_ 2332884822 D2M_Communication_State_22 "DCDC与MBMU通讯状态";
CM_ SG_ 2332884822 D2M_SUMDATA1_Reserved1_22 "预留1";
CM_ SG_ 2332884822 D2M_DCDC_PCBTemp_22 "DCDC 板温";
CM_ SG_ 2332884822 D2M_DCDC_MosTemp1_22 "DCDC 一级MOS温度";
CM_ SG_ 2332884822 D2M_DCDC_MosTemp2_22 "DCDC 二级MOS温度";
CM_ SG_ 2332884822 D2M_DCDC_TransformerTemp_22 "DCDC 变压器温度";
CM_ SG_ 2332884822 D2M_DCDC_Sleep_State_22 "DCDC休眠状态";
CM_ SG_ 2332884822 D2M_SUMDATA1_Reserved_22 "预留2";
CM_ SG_ 2332884823 D2M_SUMDATA1_CRC_23 "CRC校验";
CM_ SG_ 2332884823 D2M_SUMDATA1_DCDC_Life_23 "生命信号，0~15循环";
CM_ SG_ 2332884823 D2M_DCDC_RQ_Mode_Set_23 "预留";
CM_ SG_ 2332884823 D2M_DCDC_Work_State_23 "DCDC工作状态";
CM_ SG_ 2332884823 D2M_DCDC_AlarmSigl_State_23 "DCDC Alarm信号状态";
CM_ SG_ 2332884823 D2M_DCDC_LVPower_State_23 "DCDC低压供电电源状态";
CM_ SG_ 2332884823 D2M_DCDC_Enableline_State_23 "DCDC硬线使能信号状态(预留)";
CM_ SG_ 2332884823 D2M_Communication_State_23 "DCDC与MBMU通讯状态";
CM_ SG_ 2332884823 D2M_SUMDATA1_Reserved1_23 "预留1";
CM_ SG_ 2332884823 D2M_DCDC_PCBTemp_23 "DCDC 板温";
CM_ SG_ 2332884823 D2M_DCDC_MosTemp1_23 "DCDC 一级MOS温度";
CM_ SG_ 2332884823 D2M_DCDC_MosTemp2_23 "DCDC 二级MOS温度";
CM_ SG_ 2332884823 D2M_DCDC_TransformerTemp_23 "DCDC 变压器温度";
CM_ SG_ 2332884823 D2M_DCDC_Sleep_State_23 "DCDC休眠状态";
CM_ SG_ 2332884823 D2M_SUMDATA1_Reserved_23 "预留2";
CM_ SG_ 2332884824 D2M_SUMDATA1_CRC_24 "CRC校验";
CM_ SG_ 2332884824 D2M_SUMDATA1_DCDC_Life_24 "生命信号，0~15循环";
CM_ SG_ 2332884824 D2M_DCDC_RQ_Mode_Set_24 "预留";
CM_ SG_ 2332884824 D2M_DCDC_Work_State_24 "DCDC工作状态";
CM_ SG_ 2332884824 D2M_DCDC_AlarmSigl_State_24 "DCDC Alarm信号状态";
CM_ SG_ 2332884824 D2M_DCDC_LVPower_State_24 "DCDC低压供电电源状态";
CM_ SG_ 2332884824 D2M_DCDC_Enableline_State_24 "DCDC硬线使能信号状态(预留)";
CM_ SG_ 2332884824 D2M_Communication_State_24 "DCDC与MBMU通讯状态";
CM_ SG_ 2332884824 D2M_SUMDATA1_Reserved1_24 "预留1";
CM_ SG_ 2332884824 D2M_DCDC_PCBTemp_24 "DCDC 板温";
CM_ SG_ 2332884824 D2M_DCDC_MosTemp1_24 "DCDC 一级MOS温度";
CM_ SG_ 2332884824 D2M_DCDC_MosTemp2_24 "DCDC 二级MOS温度";
CM_ SG_ 2332884824 D2M_DCDC_TransformerTemp_24 "DCDC 变压器温度";
CM_ SG_ 2332884824 D2M_DCDC_Sleep_State_24 "DCDC休眠状态";
CM_ SG_ 2332884824 D2M_SUMDATA1_Reserved_24 "预留2";
CM_ SG_ 2332884825 D2M_SUMDATA1_CRC_25 "CRC校验";
CM_ SG_ 2332884825 D2M_SUMDATA1_DCDC_Life_25 "生命信号，0~15循环";
CM_ SG_ 2332884825 D2M_DCDC_RQ_Mode_Set_25 "预留";
CM_ SG_ 2332884825 D2M_DCDC_Work_State_25 "DCDC工作状态";
CM_ SG_ 2332884825 D2M_DCDC_AlarmSigl_State_25 "DCDC Alarm信号状态";
CM_ SG_ 2332884825 D2M_DCDC_LVPower_State_25 "DCDC低压供电电源状态";
CM_ SG_ 2332884825 D2M_DCDC_Enableline_State_25 "DCDC硬线使能信号状态(预留)";
CM_ SG_ 2332884825 D2M_Communication_State_25 "DCDC与MBMU通讯状态";
CM_ SG_ 2332884825 D2M_SUMDATA1_Reserved1_25 "预留1";
CM_ SG_ 2332884825 D2M_DCDC_PCBTemp_25 "DCDC 板温";
CM_ SG_ 2332884825 D2M_DCDC_MosTemp1_25 "DCDC 一级MOS温度";
CM_ SG_ 2332884825 D2M_DCDC_MosTemp2_25 "DCDC 二级MOS温度";
CM_ SG_ 2332884825 D2M_DCDC_TransformerTemp_25 "DCDC 变压器温度";
CM_ SG_ 2332884825 D2M_DCDC_Sleep_State_25 "DCDC休眠状态";
CM_ SG_ 2332884825 D2M_SUMDATA1_Reserved_25 "预留2";
CM_ SG_ 2332884826 D2M_SUMDATA1_CRC_26 "CRC校验";
CM_ SG_ 2332884826 D2M_SUMDATA1_DCDC_Life_26 "生命信号，0~15循环";
CM_ SG_ 2332884826 D2M_DCDC_RQ_Mode_Set_26 "预留";
CM_ SG_ 2332884826 D2M_DCDC_Work_State_26 "DCDC工作状态";
CM_ SG_ 2332884826 D2M_DCDC_AlarmSigl_State_26 "DCDC Alarm信号状态";
CM_ SG_ 2332884826 D2M_DCDC_LVPower_State_26 "DCDC低压供电电源状态";
CM_ SG_ 2332884826 D2M_DCDC_Enableline_State_26 "DCDC硬线使能信号状态(预留)";
CM_ SG_ 2332884826 D2M_Communication_State_26 "DCDC与MBMU通讯状态";
CM_ SG_ 2332884826 D2M_SUMDATA1_Reserved1_26 "预留1";
CM_ SG_ 2332884826 D2M_DCDC_PCBTemp_26 "DCDC 板温";
CM_ SG_ 2332884826 D2M_DCDC_MosTemp1_26 "DCDC 一级MOS温度";
CM_ SG_ 2332884826 D2M_DCDC_MosTemp2_26 "DCDC 二级MOS温度";
CM_ SG_ 2332884826 D2M_DCDC_TransformerTemp_26 "DCDC 变压器温度";
CM_ SG_ 2332884826 D2M_DCDC_Sleep_State_26 "DCDC休眠状态";
CM_ SG_ 2332884826 D2M_SUMDATA1_Reserved_26 "预留2";
CM_ SG_ 2332884827 D2M_SUMDATA1_CRC_27 "CRC校验";
CM_ SG_ 2332884827 D2M_SUMDATA1_DCDC_Life_27 "生命信号，0~15循环";
CM_ SG_ 2332884827 D2M_DCDC_RQ_Mode_Set_27 "预留";
CM_ SG_ 2332884827 D2M_DCDC_Work_State_27 "DCDC工作状态";
CM_ SG_ 2332884827 D2M_DCDC_AlarmSigl_State_27 "DCDC Alarm信号状态";
CM_ SG_ 2332884827 D2M_DCDC_LVPower_State_27 "DCDC低压供电电源状态";
CM_ SG_ 2332884827 D2M_DCDC_Enableline_State_27 "DCDC硬线使能信号状态(预留)";
CM_ SG_ 2332884827 D2M_Communication_State_27 "DCDC与MBMU通讯状态";
CM_ SG_ 2332884827 D2M_SUMDATA1_Reserved1_27 "预留1";
CM_ SG_ 2332884827 D2M_DCDC_PCBTemp_27 "DCDC 板温";
CM_ SG_ 2332884827 D2M_DCDC_MosTemp1_27 "DCDC 一级MOS温度";
CM_ SG_ 2332884827 D2M_DCDC_MosTemp2_27 "DCDC 二级MOS温度";
CM_ SG_ 2332884827 D2M_DCDC_TransformerTemp_27 "DCDC 变压器温度";
CM_ SG_ 2332884827 D2M_DCDC_Sleep_State_27 "DCDC休眠状态";
CM_ SG_ 2332884827 D2M_SUMDATA1_Reserved_27 "预留2";
CM_ SG_ 2332884828 D2M_SUMDATA1_CRC_28 "CRC校验";
CM_ SG_ 2332884828 D2M_SUMDATA1_DCDC_Life_28 "生命信号，0~15循环";
CM_ SG_ 2332884828 D2M_DCDC_RQ_Mode_Set_28 "预留";
CM_ SG_ 2332884828 D2M_DCDC_Work_State_28 "DCDC工作状态";
CM_ SG_ 2332884828 D2M_DCDC_AlarmSigl_State_28 "DCDC Alarm信号状态";
CM_ SG_ 2332884828 D2M_DCDC_LVPower_State_28 "DCDC低压供电电源状态";
CM_ SG_ 2332884828 D2M_DCDC_Enableline_State_28 "DCDC硬线使能信号状态(预留)";
CM_ SG_ 2332884828 D2M_Communication_State_28 "DCDC与MBMU通讯状态";
CM_ SG_ 2332884828 D2M_SUMDATA1_Reserved1_28 "预留1";
CM_ SG_ 2332884828 D2M_DCDC_PCBTemp_28 "DCDC 板温";
CM_ SG_ 2332884828 D2M_DCDC_MosTemp1_28 "DCDC 一级MOS温度";
CM_ SG_ 2332884828 D2M_DCDC_MosTemp2_28 "DCDC 二级MOS温度";
CM_ SG_ 2332884828 D2M_DCDC_TransformerTemp_28 "DCDC 变压器温度";
CM_ SG_ 2332884828 D2M_DCDC_Sleep_State_28 "DCDC休眠状态";
CM_ SG_ 2332884828 D2M_SUMDATA1_Reserved_28 "预留2";
CM_ SG_ 2332884829 D2M_SUMDATA1_CRC_29 "CRC校验";
CM_ SG_ 2332884829 D2M_SUMDATA1_DCDC_Life_29 "生命信号，0~15循环";
CM_ SG_ 2332884829 D2M_DCDC_RQ_Mode_Set_29 "预留";
CM_ SG_ 2332884829 D2M_DCDC_Work_State_29 "DCDC工作状态";
CM_ SG_ 2332884829 D2M_DCDC_AlarmSigl_State_29 "DCDC Alarm信号状态";
CM_ SG_ 2332884829 D2M_DCDC_LVPower_State_29 "DCDC低压供电电源状态";
CM_ SG_ 2332884829 D2M_DCDC_Enableline_State_29 "DCDC硬线使能信号状态(预留)";
CM_ SG_ 2332884829 D2M_Communication_State_29 "DCDC与MBMU通讯状态";
CM_ SG_ 2332884829 D2M_SUMDATA1_Reserved1_29 "预留1";
CM_ SG_ 2332884829 D2M_DCDC_PCBTemp_29 "DCDC 板温";
CM_ SG_ 2332884829 D2M_DCDC_MosTemp1_29 "DCDC 一级MOS温度";
CM_ SG_ 2332884829 D2M_DCDC_MosTemp2_29 "DCDC 二级MOS温度";
CM_ SG_ 2332884829 D2M_DCDC_TransformerTemp_29 "DCDC 变压器温度";
CM_ SG_ 2332884829 D2M_DCDC_Sleep_State_29 "DCDC休眠状态";
CM_ SG_ 2332884829 D2M_SUMDATA1_Reserved_29 "预留2";
CM_ SG_ 2332884830 D2M_SUMDATA1_CRC_30 "CRC校验";
CM_ SG_ 2332884830 D2M_SUMDATA1_DCDC_Life_30 "生命信号，0~15循环";
CM_ SG_ 2332884830 D2M_DCDC_RQ_Mode_Set_30 "预留";
CM_ SG_ 2332884830 D2M_DCDC_Work_State_30 "DCDC工作状态";
CM_ SG_ 2332884830 D2M_DCDC_AlarmSigl_State_30 "DCDC Alarm信号状态";
CM_ SG_ 2332884830 D2M_DCDC_LVPower_State_30 "DCDC低压供电电源状态";
CM_ SG_ 2332884830 D2M_DCDC_Enableline_State_30 "DCDC硬线使能信号状态(预留)";
CM_ SG_ 2332884830 D2M_Communication_State_30 "DCDC与MBMU通讯状态";
CM_ SG_ 2332884830 D2M_SUMDATA1_Reserved1_30 "预留1";
CM_ SG_ 2332884830 D2M_DCDC_PCBTemp_30 "DCDC 板温";
CM_ SG_ 2332884830 D2M_DCDC_MosTemp1_30 "DCDC 一级MOS温度";
CM_ SG_ 2332884830 D2M_DCDC_MosTemp2_30 "DCDC 二级MOS温度";
CM_ SG_ 2332884830 D2M_DCDC_TransformerTemp_30 "DCDC 变压器温度";
CM_ SG_ 2332884830 D2M_DCDC_Sleep_State_30 "DCDC休眠状态";
CM_ SG_ 2332884830 D2M_SUMDATA1_Reserved_30 "预留2";
CM_ SG_ 2332884831 D2M_SUMDATA1_CRC_31 "CRC校验";
CM_ SG_ 2332884831 D2M_SUMDATA1_DCDC_Life_31 "生命信号，0~15循环";
CM_ SG_ 2332884831 D2M_DCDC_RQ_Mode_Set_31 "预留";
CM_ SG_ 2332884831 D2M_DCDC_Work_State_31 "DCDC工作状态";
CM_ SG_ 2332884831 D2M_DCDC_AlarmSigl_State_31 "DCDC Alarm信号状态";
CM_ SG_ 2332884831 D2M_DCDC_LVPower_State_31 "DCDC低压供电电源状态";
CM_ SG_ 2332884831 D2M_DCDC_Enableline_State_31 "DCDC硬线使能信号状态(预留)";
CM_ SG_ 2332884831 D2M_Communication_State_31 "DCDC与MBMU通讯状态";
CM_ SG_ 2332884831 D2M_SUMDATA1_Reserved1_31 "预留1";
CM_ SG_ 2332884831 D2M_DCDC_PCBTemp_31 "DCDC 板温";
CM_ SG_ 2332884831 D2M_DCDC_MosTemp1_31 "DCDC 一级MOS温度";
CM_ SG_ 2332884831 D2M_DCDC_MosTemp2_31 "DCDC 二级MOS温度";
CM_ SG_ 2332884831 D2M_DCDC_TransformerTemp_31 "DCDC 变压器温度";
CM_ SG_ 2332884831 D2M_DCDC_Sleep_State_31 "DCDC休眠状态";
CM_ SG_ 2332884831 D2M_SUMDATA1_Reserved_31 "预留2";
CM_ SG_ 2332884832 D2M_SUMDATA1_CRC_32 "CRC校验";
CM_ SG_ 2332884832 D2M_SUMDATA1_DCDC_Life_32 "生命信号，0~15循环";
CM_ SG_ 2332884832 D2M_DCDC_RQ_Mode_Set_32 "预留";
CM_ SG_ 2332884832 D2M_DCDC_Work_State_32 "DCDC工作状态";
CM_ SG_ 2332884832 D2M_DCDC_AlarmSigl_State_32 "DCDC Alarm信号状态";
CM_ SG_ 2332884832 D2M_DCDC_LVPower_State_32 "DCDC低压供电电源状态";
CM_ SG_ 2332884832 D2M_DCDC_Enableline_State_32 "DCDC硬线使能信号状态(预留)";
CM_ SG_ 2332884832 D2M_Communication_State_32 "DCDC与MBMU通讯状态";
CM_ SG_ 2332884832 D2M_SUMDATA1_Reserved1_32 "预留1";
CM_ SG_ 2332884832 D2M_DCDC_PCBTemp_32 "DCDC 板温";
CM_ SG_ 2332884832 D2M_DCDC_MosTemp1_32 "DCDC 一级MOS温度";
CM_ SG_ 2332884832 D2M_DCDC_MosTemp2_32 "DCDC 二级MOS温度";
CM_ SG_ 2332884832 D2M_DCDC_TransformerTemp_32 "DCDC 变压器温度";
CM_ SG_ 2332884832 D2M_DCDC_Sleep_State_32 "DCDC休眠状态";
CM_ SG_ 2332884832 D2M_SUMDATA1_Reserved_32 "预留2";
CM_ SG_ 2332884833 D2M_SUMDATA1_CRC_33 "CRC校验";
CM_ SG_ 2332884833 D2M_SUMDATA1_DCDC_Life_33 "生命信号，0~15循环";
CM_ SG_ 2332884833 D2M_DCDC_RQ_Mode_Set_33 "预留";
CM_ SG_ 2332884833 D2M_DCDC_Work_State_33 "DCDC工作状态";
CM_ SG_ 2332884833 D2M_DCDC_AlarmSigl_State_33 "DCDC Alarm信号状态";
CM_ SG_ 2332884833 D2M_DCDC_LVPower_State_33 "DCDC低压供电电源状态";
CM_ SG_ 2332884833 D2M_DCDC_Enableline_State_33 "DCDC硬线使能信号状态(预留)";
CM_ SG_ 2332884833 D2M_Communication_State_33 "DCDC与MBMU通讯状态";
CM_ SG_ 2332884833 D2M_SUMDATA1_Reserved1_33 "预留1";
CM_ SG_ 2332884833 D2M_DCDC_PCBTemp_33 "DCDC 板温";
CM_ SG_ 2332884833 D2M_DCDC_MosTemp1_33 "DCDC 一级MOS温度";
CM_ SG_ 2332884833 D2M_DCDC_MosTemp2_33 "DCDC 二级MOS温度";
CM_ SG_ 2332884833 D2M_DCDC_TransformerTemp_33 "DCDC 变压器温度";
CM_ SG_ 2332884833 D2M_DCDC_Sleep_State_33 "DCDC休眠状态";
CM_ SG_ 2332884833 D2M_SUMDATA1_Reserved_33 "预留2";
CM_ SG_ 2332884834 D2M_SUMDATA1_CRC_34 "CRC校验";
CM_ SG_ 2332884834 D2M_SUMDATA1_DCDC_Life_34 "生命信号，0~15循环";
CM_ SG_ 2332884834 D2M_DCDC_RQ_Mode_Set_34 "预留";
CM_ SG_ 2332884834 D2M_DCDC_Work_State_34 "DCDC工作状态";
CM_ SG_ 2332884834 D2M_DCDC_AlarmSigl_State_34 "DCDC Alarm信号状态";
CM_ SG_ 2332884834 D2M_DCDC_LVPower_State_34 "DCDC低压供电电源状态";
CM_ SG_ 2332884834 D2M_DCDC_Enableline_State_34 "DCDC硬线使能信号状态(预留)";
CM_ SG_ 2332884834 D2M_Communication_State_34 "DCDC与MBMU通讯状态";
CM_ SG_ 2332884834 D2M_SUMDATA1_Reserved1_34 "预留1";
CM_ SG_ 2332884834 D2M_DCDC_PCBTemp_34 "DCDC 板温";
CM_ SG_ 2332884834 D2M_DCDC_MosTemp1_34 "DCDC 一级MOS温度";
CM_ SG_ 2332884834 D2M_DCDC_MosTemp2_34 "DCDC 二级MOS温度";
CM_ SG_ 2332884834 D2M_DCDC_TransformerTemp_34 "DCDC 变压器温度";
CM_ SG_ 2332884834 D2M_DCDC_Sleep_State_34 "DCDC休眠状态";
CM_ SG_ 2332884834 D2M_SUMDATA1_Reserved_34 "预留2";
CM_ SG_ 2332884835 D2M_SUMDATA1_CRC_35 "CRC校验";
CM_ SG_ 2332884835 D2M_SUMDATA1_DCDC_Life_35 "生命信号，0~15循环";
CM_ SG_ 2332884835 D2M_DCDC_RQ_Mode_Set_35 "预留";
CM_ SG_ 2332884835 D2M_DCDC_Work_State_35 "DCDC工作状态";
CM_ SG_ 2332884835 D2M_DCDC_AlarmSigl_State_35 "DCDC Alarm信号状态";
CM_ SG_ 2332884835 D2M_DCDC_LVPower_State_35 "DCDC低压供电电源状态";
CM_ SG_ 2332884835 D2M_DCDC_Enableline_State_35 "DCDC硬线使能信号状态(预留)";
CM_ SG_ 2332884835 D2M_Communication_State_35 "DCDC与MBMU通讯状态";
CM_ SG_ 2332884835 D2M_SUMDATA1_Reserved1_35 "预留1";
CM_ SG_ 2332884835 D2M_DCDC_PCBTemp_35 "DCDC 板温";
CM_ SG_ 2332884835 D2M_DCDC_MosTemp1_35 "DCDC 一级MOS温度";
CM_ SG_ 2332884835 D2M_DCDC_MosTemp2_35 "DCDC 二级MOS温度";
CM_ SG_ 2332884835 D2M_DCDC_TransformerTemp_35 "DCDC 变压器温度";
CM_ SG_ 2332884835 D2M_DCDC_Sleep_State_35 "DCDC休眠状态";
CM_ SG_ 2332884835 D2M_SUMDATA1_Reserved_35 "预留2";
CM_ SG_ 2332884836 D2M_SUMDATA1_CRC_36 "CRC校验";
CM_ SG_ 2332884836 D2M_SUMDATA1_DCDC_Life_36 "生命信号，0~15循环";
CM_ SG_ 2332884836 D2M_DCDC_RQ_Mode_Set_36 "预留";
CM_ SG_ 2332884836 D2M_DCDC_Work_State_36 "DCDC工作状态";
CM_ SG_ 2332884836 D2M_DCDC_AlarmSigl_State_36 "DCDC Alarm信号状态";
CM_ SG_ 2332884836 D2M_DCDC_LVPower_State_36 "DCDC低压供电电源状态";
CM_ SG_ 2332884836 D2M_DCDC_Enableline_State_36 "DCDC硬线使能信号状态(预留)";
CM_ SG_ 2332884836 D2M_Communication_State_36 "DCDC与MBMU通讯状态";
CM_ SG_ 2332884836 D2M_SUMDATA1_Reserved1_36 "预留1";
CM_ SG_ 2332884836 D2M_DCDC_PCBTemp_36 "DCDC 板温";
CM_ SG_ 2332884836 D2M_DCDC_MosTemp1_36 "DCDC 一级MOS温度";
CM_ SG_ 2332884836 D2M_DCDC_MosTemp2_36 "DCDC 二级MOS温度";
CM_ SG_ 2332884836 D2M_DCDC_TransformerTemp_36 "DCDC 变压器温度";
CM_ SG_ 2332884836 D2M_DCDC_Sleep_State_36 "DCDC休眠状态";
CM_ SG_ 2332884836 D2M_SUMDATA1_Reserved_36 "预留2";
CM_ SG_ 2332884837 D2M_SUMDATA1_CRC_37 "CRC校验";
CM_ SG_ 2332884837 D2M_SUMDATA1_DCDC_Life_37 "生命信号，0~15循环";
CM_ SG_ 2332884837 D2M_DCDC_RQ_Mode_Set_37 "预留";
CM_ SG_ 2332884837 D2M_DCDC_Work_State_37 "DCDC工作状态";
CM_ SG_ 2332884837 D2M_DCDC_AlarmSigl_State_37 "DCDC Alarm信号状态";
CM_ SG_ 2332884837 D2M_DCDC_LVPower_State_37 "DCDC低压供电电源状态";
CM_ SG_ 2332884837 D2M_DCDC_Enableline_State_37 "DCDC硬线使能信号状态(预留)";
CM_ SG_ 2332884837 D2M_Communication_State_37 "DCDC与MBMU通讯状态";
CM_ SG_ 2332884837 D2M_SUMDATA1_Reserved1_37 "预留1";
CM_ SG_ 2332884837 D2M_DCDC_PCBTemp_37 "DCDC 板温";
CM_ SG_ 2332884837 D2M_DCDC_MosTemp1_37 "DCDC 一级MOS温度";
CM_ SG_ 2332884837 D2M_DCDC_MosTemp2_37 "DCDC 二级MOS温度";
CM_ SG_ 2332884837 D2M_DCDC_TransformerTemp_37 "DCDC 变压器温度";
CM_ SG_ 2332884837 D2M_DCDC_Sleep_State_37 "DCDC休眠状态";
CM_ SG_ 2332884837 D2M_SUMDATA1_Reserved_37 "预留2";
CM_ SG_ 2332884838 D2M_SUMDATA1_CRC_38 "CRC校验";
CM_ SG_ 2332884838 D2M_SUMDATA1_DCDC_Life_38 "生命信号，0~15循环";
CM_ SG_ 2332884838 D2M_DCDC_RQ_Mode_Set_38 "预留";
CM_ SG_ 2332884838 D2M_DCDC_Work_State_38 "DCDC工作状态";
CM_ SG_ 2332884838 D2M_DCDC_AlarmSigl_State_38 "DCDC Alarm信号状态";
CM_ SG_ 2332884838 D2M_DCDC_LVPower_State_38 "DCDC低压供电电源状态";
CM_ SG_ 2332884838 D2M_DCDC_Enableline_State_38 "DCDC硬线使能信号状态(预留)";
CM_ SG_ 2332884838 D2M_Communication_State_38 "DCDC与MBMU通讯状态";
CM_ SG_ 2332884838 D2M_SUMDATA1_Reserved1_38 "预留1";
CM_ SG_ 2332884838 D2M_DCDC_PCBTemp_38 "DCDC 板温";
CM_ SG_ 2332884838 D2M_DCDC_MosTemp1_38 "DCDC 一级MOS温度";
CM_ SG_ 2332884838 D2M_DCDC_MosTemp2_38 "DCDC 二级MOS温度";
CM_ SG_ 2332884838 D2M_DCDC_TransformerTemp_38 "DCDC 变压器温度";
CM_ SG_ 2332884838 D2M_DCDC_Sleep_State_38 "DCDC休眠状态";
CM_ SG_ 2332884838 D2M_SUMDATA1_Reserved_38 "预留2";
CM_ SG_ 2332884839 D2M_SUMDATA1_CRC_39 "CRC校验";
CM_ SG_ 2332884839 D2M_SUMDATA1_DCDC_Life_39 "生命信号，0~15循环";
CM_ SG_ 2332884839 D2M_DCDC_RQ_Mode_Set_39 "预留";
CM_ SG_ 2332884839 D2M_DCDC_Work_State_39 "DCDC工作状态";
CM_ SG_ 2332884839 D2M_DCDC_AlarmSigl_State_39 "DCDC Alarm信号状态";
CM_ SG_ 2332884839 D2M_DCDC_LVPower_State_39 "DCDC低压供电电源状态";
CM_ SG_ 2332884839 D2M_DCDC_Enableline_State_39 "DCDC硬线使能信号状态(预留)";
CM_ SG_ 2332884839 D2M_Communication_State_39 "DCDC与MBMU通讯状态";
CM_ SG_ 2332884839 D2M_SUMDATA1_Reserved1_39 "预留1";
CM_ SG_ 2332884839 D2M_DCDC_PCBTemp_39 "DCDC 板温";
CM_ SG_ 2332884839 D2M_DCDC_MosTemp1_39 "DCDC 一级MOS温度";
CM_ SG_ 2332884839 D2M_DCDC_MosTemp2_39 "DCDC 二级MOS温度";
CM_ SG_ 2332884839 D2M_DCDC_TransformerTemp_39 "DCDC 变压器温度";
CM_ SG_ 2332884839 D2M_DCDC_Sleep_State_39 "DCDC休眠状态";
CM_ SG_ 2332884839 D2M_SUMDATA1_Reserved_39 "预留2";
CM_ SG_ 2332884840 D2M_SUMDATA1_CRC_40 "CRC校验";
CM_ SG_ 2332884840 D2M_SUMDATA1_DCDC_Life_40 "生命信号，0~15循环";
CM_ SG_ 2332884840 D2M_DCDC_RQ_Mode_Set_40 "预留";
CM_ SG_ 2332884840 D2M_DCDC_Work_State_40 "DCDC工作状态";
CM_ SG_ 2332884840 D2M_DCDC_AlarmSigl_State_40 "DCDC Alarm信号状态";
CM_ SG_ 2332884840 D2M_DCDC_LVPower_State_40 "DCDC低压供电电源状态";
CM_ SG_ 2332884840 D2M_DCDC_Enableline_State_40 "DCDC硬线使能信号状态(预留)";
CM_ SG_ 2332884840 D2M_Communication_State_40 "DCDC与MBMU通讯状态";
CM_ SG_ 2332884840 D2M_SUMDATA1_Reserved1_40 "预留1";
CM_ SG_ 2332884840 D2M_DCDC_PCBTemp_40 "DCDC 板温";
CM_ SG_ 2332884840 D2M_DCDC_MosTemp1_40 "DCDC 一级MOS温度";
CM_ SG_ 2332884840 D2M_DCDC_MosTemp2_40 "DCDC 二级MOS温度";
CM_ SG_ 2332884840 D2M_DCDC_TransformerTemp_40 "DCDC 变压器温度";
CM_ SG_ 2332884840 D2M_DCDC_Sleep_State_40 "DCDC休眠状态";
CM_ SG_ 2332884840 D2M_SUMDATA1_Reserved_40 "预留2";
CM_ SG_ 2332884841 D2M_SUMDATA1_CRC_41 "CRC校验";
CM_ SG_ 2332884841 D2M_SUMDATA1_DCDC_Life_41 "生命信号，0~15循环";
CM_ SG_ 2332884841 D2M_DCDC_RQ_Mode_Set_41 "预留";
CM_ SG_ 2332884841 D2M_DCDC_Work_State_41 "DCDC工作状态";
CM_ SG_ 2332884841 D2M_DCDC_AlarmSigl_State_41 "DCDC Alarm信号状态";
CM_ SG_ 2332884841 D2M_DCDC_LVPower_State_41 "DCDC低压供电电源状态";
CM_ SG_ 2332884841 D2M_DCDC_Enableline_State_41 "DCDC硬线使能信号状态(预留)";
CM_ SG_ 2332884841 D2M_Communication_State_41 "DCDC与MBMU通讯状态";
CM_ SG_ 2332884841 D2M_SUMDATA1_Reserved1_41 "预留1";
CM_ SG_ 2332884841 D2M_DCDC_PCBTemp_41 "DCDC 板温";
CM_ SG_ 2332884841 D2M_DCDC_MosTemp1_41 "DCDC 一级MOS温度";
CM_ SG_ 2332884841 D2M_DCDC_MosTemp2_41 "DCDC 二级MOS温度";
CM_ SG_ 2332884841 D2M_DCDC_TransformerTemp_41 "DCDC 变压器温度";
CM_ SG_ 2332884841 D2M_DCDC_Sleep_State_41 "DCDC休眠状态";
CM_ SG_ 2332884841 D2M_SUMDATA1_Reserved_41 "预留2";
CM_ SG_ 2332884842 D2M_SUMDATA1_CRC_42 "CRC校验";
CM_ SG_ 2332884842 D2M_SUMDATA1_DCDC_Life_42 "生命信号，0~15循环";
CM_ SG_ 2332884842 D2M_DCDC_RQ_Mode_Set_42 "预留";
CM_ SG_ 2332884842 D2M_DCDC_Work_State_42 "DCDC工作状态";
CM_ SG_ 2332884842 D2M_DCDC_AlarmSigl_State_42 "DCDC Alarm信号状态";
CM_ SG_ 2332884842 D2M_DCDC_LVPower_State_42 "DCDC低压供电电源状态";
CM_ SG_ 2332884842 D2M_DCDC_Enableline_State_42 "DCDC硬线使能信号状态(预留)";
CM_ SG_ 2332884842 D2M_Communication_State_42 "DCDC与MBMU通讯状态";
CM_ SG_ 2332884842 D2M_SUMDATA1_Reserved1_42 "预留1";
CM_ SG_ 2332884842 D2M_DCDC_PCBTemp_42 "DCDC 板温";
CM_ SG_ 2332884842 D2M_DCDC_MosTemp1_42 "DCDC 一级MOS温度";
CM_ SG_ 2332884842 D2M_DCDC_MosTemp2_42 "DCDC 二级MOS温度";
CM_ SG_ 2332884842 D2M_DCDC_TransformerTemp_42 "DCDC 变压器温度";
CM_ SG_ 2332884842 D2M_DCDC_Sleep_State_42 "DCDC休眠状态";
CM_ SG_ 2332884842 D2M_SUMDATA1_Reserved_42 "预留2";
CM_ SG_ 2332884843 D2M_SUMDATA1_CRC_43 "CRC校验";
CM_ SG_ 2332884843 D2M_SUMDATA1_DCDC_Life_43 "生命信号，0~15循环";
CM_ SG_ 2332884843 D2M_DCDC_RQ_Mode_Set_43 "预留";
CM_ SG_ 2332884843 D2M_DCDC_Work_State_43 "DCDC工作状态";
CM_ SG_ 2332884843 D2M_DCDC_AlarmSigl_State_43 "DCDC Alarm信号状态";
CM_ SG_ 2332884843 D2M_DCDC_LVPower_State_43 "DCDC低压供电电源状态";
CM_ SG_ 2332884843 D2M_DCDC_Enableline_State_43 "DCDC硬线使能信号状态(预留)";
CM_ SG_ 2332884843 D2M_Communication_State_43 "DCDC与MBMU通讯状态";
CM_ SG_ 2332884843 D2M_SUMDATA1_Reserved1_43 "预留1";
CM_ SG_ 2332884843 D2M_DCDC_PCBTemp_43 "DCDC 板温";
CM_ SG_ 2332884843 D2M_DCDC_MosTemp1_43 "DCDC 一级MOS温度";
CM_ SG_ 2332884843 D2M_DCDC_MosTemp2_43 "DCDC 二级MOS温度";
CM_ SG_ 2332884843 D2M_DCDC_TransformerTemp_43 "DCDC 变压器温度";
CM_ SG_ 2332884843 D2M_DCDC_Sleep_State_43 "DCDC休眠状态";
CM_ SG_ 2332884843 D2M_SUMDATA1_Reserved_43 "预留2";
CM_ SG_ 2332884844 D2M_SUMDATA1_CRC_44 "CRC校验";
CM_ SG_ 2332884844 D2M_SUMDATA1_DCDC_Life_44 "生命信号，0~15循环";
CM_ SG_ 2332884844 D2M_DCDC_RQ_Mode_Set_44 "预留";
CM_ SG_ 2332884844 D2M_DCDC_Work_State_44 "DCDC工作状态";
CM_ SG_ 2332884844 D2M_DCDC_AlarmSigl_State_44 "DCDC Alarm信号状态";
CM_ SG_ 2332884844 D2M_DCDC_LVPower_State_44 "DCDC低压供电电源状态";
CM_ SG_ 2332884844 D2M_DCDC_Enableline_State_44 "DCDC硬线使能信号状态(预留)";
CM_ SG_ 2332884844 D2M_Communication_State_44 "DCDC与MBMU通讯状态";
CM_ SG_ 2332884844 D2M_SUMDATA1_Reserved1_44 "预留1";
CM_ SG_ 2332884844 D2M_DCDC_PCBTemp_44 "DCDC 板温";
CM_ SG_ 2332884844 D2M_DCDC_MosTemp1_44 "DCDC 一级MOS温度";
CM_ SG_ 2332884844 D2M_DCDC_MosTemp2_44 "DCDC 二级MOS温度";
CM_ SG_ 2332884844 D2M_DCDC_TransformerTemp_44 "DCDC 变压器温度";
CM_ SG_ 2332884844 D2M_DCDC_Sleep_State_44 "DCDC休眠状态";
CM_ SG_ 2332884844 D2M_SUMDATA1_Reserved_44 "预留2";
CM_ SG_ 2332884845 D2M_SUMDATA1_CRC_45 "CRC校验";
CM_ SG_ 2332884845 D2M_SUMDATA1_DCDC_Life_45 "生命信号，0~15循环";
CM_ SG_ 2332884845 D2M_DCDC_RQ_Mode_Set_45 "预留";
CM_ SG_ 2332884845 D2M_DCDC_Work_State_45 "DCDC工作状态";
CM_ SG_ 2332884845 D2M_DCDC_AlarmSigl_State_45 "DCDC Alarm信号状态";
CM_ SG_ 2332884845 D2M_DCDC_LVPower_State_45 "DCDC低压供电电源状态";
CM_ SG_ 2332884845 D2M_DCDC_Enableline_State_45 "DCDC硬线使能信号状态(预留)";
CM_ SG_ 2332884845 D2M_Communication_State_45 "DCDC与MBMU通讯状态";
CM_ SG_ 2332884845 D2M_SUMDATA1_Reserved1_45 "预留1";
CM_ SG_ 2332884845 D2M_DCDC_PCBTemp_45 "DCDC 板温";
CM_ SG_ 2332884845 D2M_DCDC_MosTemp1_45 "DCDC 一级MOS温度";
CM_ SG_ 2332884845 D2M_DCDC_MosTemp2_45 "DCDC 二级MOS温度";
CM_ SG_ 2332884845 D2M_DCDC_TransformerTemp_45 "DCDC 变压器温度";
CM_ SG_ 2332884845 D2M_DCDC_Sleep_State_45 "DCDC休眠状态";
CM_ SG_ 2332884845 D2M_SUMDATA1_Reserved_45 "预留2";
CM_ SG_ 2332884846 D2M_SUMDATA1_CRC_46 "CRC校验";
CM_ SG_ 2332884846 D2M_SUMDATA1_DCDC_Life_46 "生命信号，0~15循环";
CM_ SG_ 2332884846 D2M_DCDC_RQ_Mode_Set_46 "预留";
CM_ SG_ 2332884846 D2M_DCDC_Work_State_46 "DCDC工作状态";
CM_ SG_ 2332884846 D2M_DCDC_AlarmSigl_State_46 "DCDC Alarm信号状态";
CM_ SG_ 2332884846 D2M_DCDC_LVPower_State_46 "DCDC低压供电电源状态";
CM_ SG_ 2332884846 D2M_DCDC_Enableline_State_46 "DCDC硬线使能信号状态(预留)";
CM_ SG_ 2332884846 D2M_Communication_State_46 "DCDC与MBMU通讯状态";
CM_ SG_ 2332884846 D2M_SUMDATA1_Reserved1_46 "预留1";
CM_ SG_ 2332884846 D2M_DCDC_PCBTemp_46 "DCDC 板温";
CM_ SG_ 2332884846 D2M_DCDC_MosTemp1_46 "DCDC 一级MOS温度";
CM_ SG_ 2332884846 D2M_DCDC_MosTemp2_46 "DCDC 二级MOS温度";
CM_ SG_ 2332884846 D2M_DCDC_TransformerTemp_46 "DCDC 变压器温度";
CM_ SG_ 2332884846 D2M_DCDC_Sleep_State_46 "DCDC休眠状态";
CM_ SG_ 2332884846 D2M_SUMDATA1_Reserved_46 "预留2";
CM_ SG_ 2332884847 D2M_SUMDATA1_CRC_47 "CRC校验";
CM_ SG_ 2332884847 D2M_SUMDATA1_DCDC_Life_47 "生命信号，0~15循环";
CM_ SG_ 2332884847 D2M_DCDC_RQ_Mode_Set_47 "预留";
CM_ SG_ 2332884847 D2M_DCDC_Work_State_47 "DCDC工作状态";
CM_ SG_ 2332884847 D2M_DCDC_AlarmSigl_State_47 "DCDC Alarm信号状态";
CM_ SG_ 2332884847 D2M_DCDC_LVPower_State_47 "DCDC低压供电电源状态";
CM_ SG_ 2332884847 D2M_DCDC_Enableline_State_47 "DCDC硬线使能信号状态(预留)";
CM_ SG_ 2332884847 D2M_Communication_State_47 "DCDC与MBMU通讯状态";
CM_ SG_ 2332884847 D2M_SUMDATA1_Reserved1_47 "预留1";
CM_ SG_ 2332884847 D2M_DCDC_PCBTemp_47 "DCDC 板温";
CM_ SG_ 2332884847 D2M_DCDC_MosTemp1_47 "DCDC 一级MOS温度";
CM_ SG_ 2332884847 D2M_DCDC_MosTemp2_47 "DCDC 二级MOS温度";
CM_ SG_ 2332884847 D2M_DCDC_TransformerTemp_47 "DCDC 变压器温度";
CM_ SG_ 2332884847 D2M_DCDC_Sleep_State_47 "DCDC休眠状态";
CM_ SG_ 2332884847 D2M_SUMDATA1_Reserved_47 "预留2";
CM_ SG_ 2332884848 D2M_SUMDATA1_CRC_48 "CRC校验";
CM_ SG_ 2332884848 D2M_SUMDATA1_DCDC_Life_48 "生命信号，0~15循环";
CM_ SG_ 2332884848 D2M_DCDC_RQ_Mode_Set_48 "预留";
CM_ SG_ 2332884848 D2M_DCDC_Work_State_48 "DCDC工作状态";
CM_ SG_ 2332884848 D2M_DCDC_AlarmSigl_State_48 "DCDC Alarm信号状态";
CM_ SG_ 2332884848 D2M_DCDC_LVPower_State_48 "DCDC低压供电电源状态";
CM_ SG_ 2332884848 D2M_DCDC_Enableline_State_48 "DCDC硬线使能信号状态(预留)";
CM_ SG_ 2332884848 D2M_Communication_State_48 "DCDC与MBMU通讯状态";
CM_ SG_ 2332884848 D2M_SUMDATA1_Reserved1_48 "预留1";
CM_ SG_ 2332884848 D2M_DCDC_PCBTemp_48 "DCDC 板温";
CM_ SG_ 2332884848 D2M_DCDC_MosTemp1_48 "DCDC 一级MOS温度";
CM_ SG_ 2332884848 D2M_DCDC_MosTemp2_48 "DCDC 二级MOS温度";
CM_ SG_ 2332884848 D2M_DCDC_TransformerTemp_48 "DCDC 变压器温度";
CM_ SG_ 2332884848 D2M_DCDC_Sleep_State_48 "DCDC休眠状态";
CM_ SG_ 2332884848 D2M_SUMDATA1_Reserved_48 "预留2";
CM_ SG_ 2332884849 D2M_SUMDATA1_CRC_49 "CRC校验";
CM_ SG_ 2332884849 D2M_SUMDATA1_DCDC_Life_49 "生命信号，0~15循环";
CM_ SG_ 2332884849 D2M_DCDC_RQ_Mode_Set_49 "预留";
CM_ SG_ 2332884849 D2M_DCDC_Work_State_49 "DCDC工作状态";
CM_ SG_ 2332884849 D2M_DCDC_AlarmSigl_State_49 "DCDC Alarm信号状态";
CM_ SG_ 2332884849 D2M_DCDC_LVPower_State_49 "DCDC低压供电电源状态";
CM_ SG_ 2332884849 D2M_DCDC_Enableline_State_49 "DCDC硬线使能信号状态(预留)";
CM_ SG_ 2332884849 D2M_Communication_State_49 "DCDC与MBMU通讯状态";
CM_ SG_ 2332884849 D2M_SUMDATA1_Reserved1_49 "预留1";
CM_ SG_ 2332884849 D2M_DCDC_PCBTemp_49 "DCDC 板温";
CM_ SG_ 2332884849 D2M_DCDC_MosTemp1_49 "DCDC 一级MOS温度";
CM_ SG_ 2332884849 D2M_DCDC_MosTemp2_49 "DCDC 二级MOS温度";
CM_ SG_ 2332884849 D2M_DCDC_TransformerTemp_49 "DCDC 变压器温度";
CM_ SG_ 2332884849 D2M_DCDC_Sleep_State_49 "DCDC休眠状态";
CM_ SG_ 2332884849 D2M_SUMDATA1_Reserved_49 "预留2";
CM_ SG_ 2332884850 D2M_SUMDATA1_CRC_50 "CRC校验";
CM_ SG_ 2332884850 D2M_SUMDATA1_DCDC_Life_50 "生命信号，0~15循环";
CM_ SG_ 2332884850 D2M_DCDC_RQ_Mode_Set_50 "预留";
CM_ SG_ 2332884850 D2M_DCDC_Work_State_50 "DCDC工作状态";
CM_ SG_ 2332884850 D2M_DCDC_AlarmSigl_State_50 "DCDC Alarm信号状态";
CM_ SG_ 2332884850 D2M_DCDC_LVPower_State_50 "DCDC低压供电电源状态";
CM_ SG_ 2332884850 D2M_DCDC_Enableline_State_50 "DCDC硬线使能信号状态(预留)";
CM_ SG_ 2332884850 D2M_Communication_State_50 "DCDC与MBMU通讯状态";
CM_ SG_ 2332884850 D2M_SUMDATA1_Reserved1_50 "预留1";
CM_ SG_ 2332884850 D2M_DCDC_PCBTemp_50 "DCDC 板温";
CM_ SG_ 2332884850 D2M_DCDC_MosTemp1_50 "DCDC 一级MOS温度";
CM_ SG_ 2332884850 D2M_DCDC_MosTemp2_50 "DCDC 二级MOS温度";
CM_ SG_ 2332884850 D2M_DCDC_TransformerTemp_50 "DCDC 变压器温度";
CM_ SG_ 2332884850 D2M_DCDC_Sleep_State_50 "DCDC休眠状态";
CM_ SG_ 2332884850 D2M_SUMDATA1_Reserved_50 "预留2";
CM_ SG_ 2332884851 D2M_SUMDATA1_CRC_51 "CRC校验";
CM_ SG_ 2332884851 D2M_SUMDATA1_DCDC_Life_51 "生命信号，0~15循环";
CM_ SG_ 2332884851 D2M_DCDC_RQ_Mode_Set_51 "预留";
CM_ SG_ 2332884851 D2M_DCDC_Work_State_51 "DCDC工作状态";
CM_ SG_ 2332884851 D2M_DCDC_AlarmSigl_State_51 "DCDC Alarm信号状态";
CM_ SG_ 2332884851 D2M_DCDC_LVPower_State_51 "DCDC低压供电电源状态";
CM_ SG_ 2332884851 D2M_DCDC_Enableline_State_51 "DCDC硬线使能信号状态(预留)";
CM_ SG_ 2332884851 D2M_Communication_State_51 "DCDC与MBMU通讯状态";
CM_ SG_ 2332884851 D2M_SUMDATA1_Reserved1_51 "预留1";
CM_ SG_ 2332884851 D2M_DCDC_PCBTemp_51 "DCDC 板温";
CM_ SG_ 2332884851 D2M_DCDC_MosTemp1_51 "DCDC 一级MOS温度";
CM_ SG_ 2332884851 D2M_DCDC_MosTemp2_51 "DCDC 二级MOS温度";
CM_ SG_ 2332884851 D2M_DCDC_TransformerTemp_51 "DCDC 变压器温度";
CM_ SG_ 2332884851 D2M_DCDC_Sleep_State_51 "DCDC休眠状态";
CM_ SG_ 2332884851 D2M_SUMDATA1_Reserved_51 "预留2";
CM_ SG_ 2332884852 D2M_SUMDATA1_CRC_52 "CRC校验";
CM_ SG_ 2332884852 D2M_SUMDATA1_DCDC_Life_52 "生命信号，0~15循环";
CM_ SG_ 2332884852 D2M_DCDC_RQ_Mode_Set_52 "预留";
CM_ SG_ 2332884852 D2M_DCDC_Work_State_52 "DCDC工作状态";
CM_ SG_ 2332884852 D2M_DCDC_AlarmSigl_State_52 "DCDC Alarm信号状态";
CM_ SG_ 2332884852 D2M_DCDC_LVPower_State_52 "DCDC低压供电电源状态";
CM_ SG_ 2332884852 D2M_DCDC_Enableline_State_52 "DCDC硬线使能信号状态(预留)";
CM_ SG_ 2332884852 D2M_Communication_State_52 "DCDC与MBMU通讯状态";
CM_ SG_ 2332884852 D2M_SUMDATA1_Reserved1_52 "预留1";
CM_ SG_ 2332884852 D2M_DCDC_PCBTemp_52 "DCDC 板温";
CM_ SG_ 2332884852 D2M_DCDC_MosTemp1_52 "DCDC 一级MOS温度";
CM_ SG_ 2332884852 D2M_DCDC_MosTemp2_52 "DCDC 二级MOS温度";
CM_ SG_ 2332884852 D2M_DCDC_TransformerTemp_52 "DCDC 变压器温度";
CM_ SG_ 2332884852 D2M_DCDC_Sleep_State_52 "DCDC休眠状态";
CM_ SG_ 2332884852 D2M_SUMDATA1_Reserved_52 "预留2";
VAL_ 2332884801 D2M_DCDC_Work_State_01 0 "Standby" 1 "Normal Run" 2 "Bypass" 3 "Fault" ;
VAL_ 2332884801 D2M_DCDC_AlarmSigl_State_01 0 "No alarm" 1 "Alarm occur（告警信号拉低时）" ;
VAL_ 2332884801 D2M_DCDC_LVPower_State_01 0 "Off" 1 "On" ;
VAL_ 2332884801 D2M_DCDC_Enableline_State_01 0 "Disable" 1 "Enable" ;
VAL_ 2332884801 D2M_Communication_State_01 0 "Normal" 1 "CAN lost" ;
VAL_ 2332884801 D2M_DCDC_Sleep_State_01 0 "未休眠" 1 "休眠" ;
VAL_ 2332884802 D2M_DCDC_Work_State_02 0 "Standby" 1 "Normal Run" 2 "Bypass" 3 "Fault" ;
VAL_ 2332884802 D2M_DCDC_AlarmSigl_State_02 0 "No alarm" 1 "Alarm occur（告警信号拉低时）" ;
VAL_ 2332884802 D2M_DCDC_LVPower_State_02 0 "Off" 1 "On" ;
VAL_ 2332884802 D2M_DCDC_Enableline_State_02 0 "Disable" 1 "Enable" ;
VAL_ 2332884802 D2M_Communication_State_02 0 "Normal" 1 "CAN lost" ;
VAL_ 2332884802 D2M_DCDC_Sleep_State_02 0 "未休眠" 1 "休眠" ;
VAL_ 2332884803 D2M_DCDC_Work_State_03 0 "Standby" 1 "Normal Run" 2 "Bypass" 3 "Fault" ;
VAL_ 2332884803 D2M_DCDC_AlarmSigl_State_03 0 "No alarm" 1 "Alarm occur（告警信号拉低时）" ;
VAL_ 2332884803 D2M_DCDC_LVPower_State_03 0 "Off" 1 "On" ;
VAL_ 2332884803 D2M_DCDC_Enableline_State_03 0 "Disable" 1 "Enable" ;
VAL_ 2332884803 D2M_Communication_State_03 0 "Normal" 1 "CAN lost" ;
VAL_ 2332884803 D2M_DCDC_Sleep_State_03 0 "未休眠" 1 "休眠" ;
VAL_ 2332884804 D2M_DCDC_Work_State_04 0 "Standby" 1 "Normal Run" 2 "Bypass" 3 "Fault" ;
VAL_ 2332884804 D2M_DCDC_AlarmSigl_State_04 0 "No alarm" 1 "Alarm occur（告警信号拉低时）" ;
VAL_ 2332884804 D2M_DCDC_LVPower_State_04 0 "Off" 1 "On" ;
VAL_ 2332884804 D2M_DCDC_Enableline_State_04 0 "Disable" 1 "Enable" ;
VAL_ 2332884804 D2M_Communication_State_04 0 "Normal" 1 "CAN lost" ;
VAL_ 2332884804 D2M_DCDC_Sleep_State_04 0 "未休眠" 1 "休眠" ;
VAL_ 2332884805 D2M_DCDC_Work_State_05 0 "Standby" 1 "Normal Run" 2 "Bypass" 3 "Fault" ;
VAL_ 2332884805 D2M_DCDC_AlarmSigl_State_05 0 "No alarm" 1 "Alarm occur（告警信号拉低时）" ;
VAL_ 2332884805 D2M_DCDC_LVPower_State_05 0 "Off" 1 "On" ;
VAL_ 2332884805 D2M_DCDC_Enableline_State_05 0 "Disable" 1 "Enable" ;
VAL_ 2332884805 D2M_Communication_State_05 0 "Normal" 1 "CAN lost" ;
VAL_ 2332884805 D2M_DCDC_Sleep_State_05 0 "未休眠" 1 "休眠" ;
VAL_ 2332884806 D2M_DCDC_Work_State_06 0 "Standby" 1 "Normal Run" 2 "Bypass" 3 "Fault" ;
VAL_ 2332884806 D2M_DCDC_AlarmSigl_State_06 0 "No alarm" 1 "Alarm occur（告警信号拉低时）" ;
VAL_ 2332884806 D2M_DCDC_LVPower_State_06 0 "Off" 1 "On" ;
VAL_ 2332884806 D2M_DCDC_Enableline_State_06 0 "Disable" 1 "Enable" ;
VAL_ 2332884806 D2M_Communication_State_06 0 "Normal" 1 "CAN lost" ;
VAL_ 2332884806 D2M_DCDC_Sleep_State_06 0 "未休眠" 1 "休眠" ;
VAL_ 2332884807 D2M_DCDC_Work_State_07 0 "Standby" 1 "Normal Run" 2 "Bypass" 3 "Fault" ;
VAL_ 2332884807 D2M_DCDC_AlarmSigl_State_07 0 "No alarm" 1 "Alarm occur（告警信号拉低时）" ;
VAL_ 2332884807 D2M_DCDC_LVPower_State_07 0 "Off" 1 "On" ;
VAL_ 2332884807 D2M_DCDC_Enableline_State_07 0 "Disable" 1 "Enable" ;
VAL_ 2332884807 D2M_Communication_State_07 0 "Normal" 1 "CAN lost" ;
VAL_ 2332884807 D2M_DCDC_Sleep_State_07 0 "未休眠" 1 "休眠" ;
VAL_ 2332884808 D2M_DCDC_Work_State_08 0 "Standby" 1 "Normal Run" 2 "Bypass" 3 "Fault" ;
VAL_ 2332884808 D2M_DCDC_AlarmSigl_State_08 0 "No alarm" 1 "Alarm occur（告警信号拉低时）" ;
VAL_ 2332884808 D2M_DCDC_LVPower_State_08 0 "Off" 1 "On" ;
VAL_ 2332884808 D2M_DCDC_Enableline_State_08 0 "Disable" 1 "Enable" ;
VAL_ 2332884808 D2M_Communication_State_08 0 "Normal" 1 "CAN lost" ;
VAL_ 2332884808 D2M_DCDC_Sleep_State_08 0 "未休眠" 1 "休眠" ;
VAL_ 2332884809 D2M_DCDC_Work_State_09 0 "Standby" 1 "Normal Run" 2 "Bypass" 3 "Fault" ;
VAL_ 2332884809 D2M_DCDC_AlarmSigl_State_09 0 "No alarm" 1 "Alarm occur（告警信号拉低时）" ;
VAL_ 2332884809 D2M_DCDC_LVPower_State_09 0 "Off" 1 "On" ;
VAL_ 2332884809 D2M_DCDC_Enableline_State_09 0 "Disable" 1 "Enable" ;
VAL_ 2332884809 D2M_Communication_State_09 0 "Normal" 1 "CAN lost" ;
VAL_ 2332884809 D2M_DCDC_Sleep_State_09 0 "未休眠" 1 "休眠" ;
VAL_ 2332884810 D2M_DCDC_Work_State_10 0 "Standby" 1 "Normal Run" 2 "Bypass" 3 "Fault" ;
VAL_ 2332884810 D2M_DCDC_AlarmSigl_State_10 0 "No alarm" 1 "Alarm occur（告警信号拉低时）" ;
VAL_ 2332884810 D2M_DCDC_LVPower_State_10 0 "Off" 1 "On" ;
VAL_ 2332884810 D2M_DCDC_Enableline_State_10 0 "Disable" 1 "Enable" ;
VAL_ 2332884810 D2M_Communication_State_10 0 "Normal" 1 "CAN lost" ;
VAL_ 2332884810 D2M_DCDC_Sleep_State_10 0 "未休眠" 1 "休眠" ;
VAL_ 2332884811 D2M_DCDC_Work_State_11 0 "Standby" 1 "Normal Run" 2 "Bypass" 3 "Fault" ;
VAL_ 2332884811 D2M_DCDC_AlarmSigl_State_11 0 "No alarm" 1 "Alarm occur（告警信号拉低时）" ;
VAL_ 2332884811 D2M_DCDC_LVPower_State_11 0 "Off" 1 "On" ;
VAL_ 2332884811 D2M_DCDC_Enableline_State_11 0 "Disable" 1 "Enable" ;
VAL_ 2332884811 D2M_Communication_State_11 0 "Normal" 1 "CAN lost" ;
VAL_ 2332884811 D2M_DCDC_Sleep_State_11 0 "未休眠" 1 "休眠" ;
VAL_ 2332884812 D2M_DCDC_Work_State_12 0 "Standby" 1 "Normal Run" 2 "Bypass" 3 "Fault" ;
VAL_ 2332884812 D2M_DCDC_AlarmSigl_State_12 0 "No alarm" 1 "Alarm occur（告警信号拉低时）" ;
VAL_ 2332884812 D2M_DCDC_LVPower_State_12 0 "Off" 1 "On" ;
VAL_ 2332884812 D2M_DCDC_Enableline_State_12 0 "Disable" 1 "Enable" ;
VAL_ 2332884812 D2M_Communication_State_12 0 "Normal" 1 "CAN lost" ;
VAL_ 2332884812 D2M_DCDC_Sleep_State_12 0 "未休眠" 1 "休眠" ;
VAL_ 2332884813 D2M_DCDC_Work_State_13 0 "Standby" 1 "Normal Run" 2 "Bypass" 3 "Fault" ;
VAL_ 2332884813 D2M_DCDC_AlarmSigl_State_13 0 "No alarm" 1 "Alarm occur（告警信号拉低时）" ;
VAL_ 2332884813 D2M_DCDC_LVPower_State_13 0 "Off" 1 "On" ;
VAL_ 2332884813 D2M_DCDC_Enableline_State_13 0 "Disable" 1 "Enable" ;
VAL_ 2332884813 D2M_Communication_State_13 0 "Normal" 1 "CAN lost" ;
VAL_ 2332884813 D2M_DCDC_Sleep_State_13 0 "未休眠" 1 "休眠" ;
VAL_ 2332884814 D2M_DCDC_Work_State_14 0 "Standby" 1 "Normal Run" 2 "Bypass" 3 "Fault" ;
VAL_ 2332884814 D2M_DCDC_AlarmSigl_State_14 0 "No alarm" 1 "Alarm occur（告警信号拉低时）" ;
VAL_ 2332884814 D2M_DCDC_LVPower_State_14 0 "Off" 1 "On" ;
VAL_ 2332884814 D2M_DCDC_Enableline_State_14 0 "Disable" 1 "Enable" ;
VAL_ 2332884814 D2M_Communication_State_14 0 "Normal" 1 "CAN lost" ;
VAL_ 2332884814 D2M_DCDC_Sleep_State_14 0 "未休眠" 1 "休眠" ;
VAL_ 2332884815 D2M_DCDC_Work_State_15 0 "Standby" 1 "Normal Run" 2 "Bypass" 3 "Fault" ;
VAL_ 2332884815 D2M_DCDC_AlarmSigl_State_15 0 "No alarm" 1 "Alarm occur（告警信号拉低时）" ;
VAL_ 2332884815 D2M_DCDC_LVPower_State_15 0 "Off" 1 "On" ;
VAL_ 2332884815 D2M_DCDC_Enableline_State_15 0 "Disable" 1 "Enable" ;
VAL_ 2332884815 D2M_Communication_State_15 0 "Normal" 1 "CAN lost" ;
VAL_ 2332884815 D2M_DCDC_Sleep_State_15 0 "未休眠" 1 "休眠" ;
VAL_ 2332884816 D2M_DCDC_Work_State_16 0 "Standby" 1 "Normal Run" 2 "Bypass" 3 "Fault" ;
VAL_ 2332884816 D2M_DCDC_AlarmSigl_State_16 0 "No alarm" 1 "Alarm occur（告警信号拉低时）" ;
VAL_ 2332884816 D2M_DCDC_LVPower_State_16 0 "Off" 1 "On" ;
VAL_ 2332884816 D2M_DCDC_Enableline_State_16 0 "Disable" 1 "Enable" ;
VAL_ 2332884816 D2M_Communication_State_16 0 "Normal" 1 "CAN lost" ;
VAL_ 2332884816 D2M_DCDC_Sleep_State_16 0 "未休眠" 1 "休眠" ;
VAL_ 2332884817 D2M_DCDC_Work_State_17 0 "Standby" 1 "Normal Run" 2 "Bypass" 3 "Fault" ;
VAL_ 2332884817 D2M_DCDC_AlarmSigl_State_17 0 "No alarm" 1 "Alarm occur（告警信号拉低时）" ;
VAL_ 2332884817 D2M_DCDC_LVPower_State_17 0 "Off" 1 "On" ;
VAL_ 2332884817 D2M_DCDC_Enableline_State_17 0 "Disable" 1 "Enable" ;
VAL_ 2332884817 D2M_Communication_State_17 0 "Normal" 1 "CAN lost" ;
VAL_ 2332884817 D2M_DCDC_Sleep_State_17 0 "未休眠" 1 "休眠" ;
VAL_ 2332884818 D2M_DCDC_Work_State_18 0 "Standby" 1 "Normal Run" 2 "Bypass" 3 "Fault" ;
VAL_ 2332884818 D2M_DCDC_AlarmSigl_State_18 0 "No alarm" 1 "Alarm occur（告警信号拉低时）" ;
VAL_ 2332884818 D2M_DCDC_LVPower_State_18 0 "Off" 1 "On" ;
VAL_ 2332884818 D2M_DCDC_Enableline_State_18 0 "Disable" 1 "Enable" ;
VAL_ 2332884818 D2M_Communication_State_18 0 "Normal" 1 "CAN lost" ;
VAL_ 2332884818 D2M_DCDC_Sleep_State_18 0 "未休眠" 1 "休眠" ;
VAL_ 2332884819 D2M_DCDC_Work_State_19 0 "Standby" 1 "Normal Run" 2 "Bypass" 3 "Fault" ;
VAL_ 2332884819 D2M_DCDC_AlarmSigl_State_19 0 "No alarm" 1 "Alarm occur（告警信号拉低时）" ;
VAL_ 2332884819 D2M_DCDC_LVPower_State_19 0 "Off" 1 "On" ;
VAL_ 2332884819 D2M_DCDC_Enableline_State_19 0 "Disable" 1 "Enable" ;
VAL_ 2332884819 D2M_Communication_State_19 0 "Normal" 1 "CAN lost" ;
VAL_ 2332884819 D2M_DCDC_Sleep_State_19 0 "未休眠" 1 "休眠" ;
VAL_ 2332884820 D2M_DCDC_Work_State_20 0 "Standby" 1 "Normal Run" 2 "Bypass" 3 "Fault" ;
VAL_ 2332884820 D2M_DCDC_AlarmSigl_State_20 0 "No alarm" 1 "Alarm occur（告警信号拉低时）" ;
VAL_ 2332884820 D2M_DCDC_LVPower_State_20 0 "Off" 1 "On" ;
VAL_ 2332884820 D2M_DCDC_Enableline_State_20 0 "Disable" 1 "Enable" ;
VAL_ 2332884820 D2M_Communication_State_20 0 "Normal" 1 "CAN lost" ;
VAL_ 2332884820 D2M_DCDC_Sleep_State_20 0 "未休眠" 1 "休眠" ;
VAL_ 2332884821 D2M_DCDC_Work_State_21 0 "Standby" 1 "Normal Run" 2 "Bypass" 3 "Fault" ;
VAL_ 2332884821 D2M_DCDC_AlarmSigl_State_21 0 "No alarm" 1 "Alarm occur（告警信号拉低时）" ;
VAL_ 2332884821 D2M_DCDC_LVPower_State_21 0 "Off" 1 "On" ;
VAL_ 2332884821 D2M_DCDC_Enableline_State_21 0 "Disable" 1 "Enable" ;
VAL_ 2332884821 D2M_Communication_State_21 0 "Normal" 1 "CAN lost" ;
VAL_ 2332884821 D2M_DCDC_Sleep_State_21 0 "未休眠" 1 "休眠" ;
VAL_ 2332884822 D2M_DCDC_Work_State_22 0 "Standby" 1 "Normal Run" 2 "Bypass" 3 "Fault" ;
VAL_ 2332884822 D2M_DCDC_AlarmSigl_State_22 0 "No alarm" 1 "Alarm occur（告警信号拉低时）" ;
VAL_ 2332884822 D2M_DCDC_LVPower_State_22 0 "Off" 1 "On" ;
VAL_ 2332884822 D2M_DCDC_Enableline_State_22 0 "Disable" 1 "Enable" ;
VAL_ 2332884822 D2M_Communication_State_22 0 "Normal" 1 "CAN lost" ;
VAL_ 2332884822 D2M_DCDC_Sleep_State_22 0 "未休眠" 1 "休眠" ;
VAL_ 2332884823 D2M_DCDC_Work_State_23 0 "Standby" 1 "Normal Run" 2 "Bypass" 3 "Fault" ;
VAL_ 2332884823 D2M_DCDC_AlarmSigl_State_23 0 "No alarm" 1 "Alarm occur（告警信号拉低时）" ;
VAL_ 2332884823 D2M_DCDC_LVPower_State_23 0 "Off" 1 "On" ;
VAL_ 2332884823 D2M_DCDC_Enableline_State_23 0 "Disable" 1 "Enable" ;
VAL_ 2332884823 D2M_Communication_State_23 0 "Normal" 1 "CAN lost" ;
VAL_ 2332884823 D2M_DCDC_Sleep_State_23 0 "未休眠" 1 "休眠" ;
VAL_ 2332884824 D2M_DCDC_Work_State_24 0 "Standby" 1 "Normal Run" 2 "Bypass" 3 "Fault" ;
VAL_ 2332884824 D2M_DCDC_AlarmSigl_State_24 0 "No alarm" 1 "Alarm occur（告警信号拉低时）" ;
VAL_ 2332884824 D2M_DCDC_LVPower_State_24 0 "Off" 1 "On" ;
VAL_ 2332884824 D2M_DCDC_Enableline_State_24 0 "Disable" 1 "Enable" ;
VAL_ 2332884824 D2M_Communication_State_24 0 "Normal" 1 "CAN lost" ;
VAL_ 2332884824 D2M_DCDC_Sleep_State_24 0 "未休眠" 1 "休眠" ;
VAL_ 2332884825 D2M_DCDC_Work_State_25 0 "Standby" 1 "Normal Run" 2 "Bypass" 3 "Fault" ;
VAL_ 2332884825 D2M_DCDC_AlarmSigl_State_25 0 "No alarm" 1 "Alarm occur（告警信号拉低时）" ;
VAL_ 2332884825 D2M_DCDC_LVPower_State_25 0 "Off" 1 "On" ;
VAL_ 2332884825 D2M_DCDC_Enableline_State_25 0 "Disable" 1 "Enable" ;
VAL_ 2332884825 D2M_Communication_State_25 0 "Normal" 1 "CAN lost" ;
VAL_ 2332884825 D2M_DCDC_Sleep_State_25 0 "未休眠" 1 "休眠" ;
VAL_ 2332884826 D2M_DCDC_Work_State_26 0 "Standby" 1 "Normal Run" 2 "Bypass" 3 "Fault" ;
VAL_ 2332884826 D2M_DCDC_AlarmSigl_State_26 0 "No alarm" 1 "Alarm occur（告警信号拉低时）" ;
VAL_ 2332884826 D2M_DCDC_LVPower_State_26 0 "Off" 1 "On" ;
VAL_ 2332884826 D2M_DCDC_Enableline_State_26 0 "Disable" 1 "Enable" ;
VAL_ 2332884826 D2M_Communication_State_26 0 "Normal" 1 "CAN lost" ;
VAL_ 2332884826 D2M_DCDC_Sleep_State_26 0 "未休眠" 1 "休眠" ;
VAL_ 2332884827 D2M_DCDC_Work_State_27 0 "Standby" 1 "Normal Run" 2 "Bypass" 3 "Fault" ;
VAL_ 2332884827 D2M_DCDC_AlarmSigl_State_27 0 "No alarm" 1 "Alarm occur（告警信号拉低时）" ;
VAL_ 2332884827 D2M_DCDC_LVPower_State_27 0 "Off" 1 "On" ;
VAL_ 2332884827 D2M_DCDC_Enableline_State_27 0 "Disable" 1 "Enable" ;
VAL_ 2332884827 D2M_Communication_State_27 0 "Normal" 1 "CAN lost" ;
VAL_ 2332884827 D2M_DCDC_Sleep_State_27 0 "未休眠" 1 "休眠" ;
VAL_ 2332884828 D2M_DCDC_Work_State_28 0 "Standby" 1 "Normal Run" 2 "Bypass" 3 "Fault" ;
VAL_ 2332884828 D2M_DCDC_AlarmSigl_State_28 0 "No alarm" 1 "Alarm occur（告警信号拉低时）" ;
VAL_ 2332884828 D2M_DCDC_LVPower_State_28 0 "Off" 1 "On" ;
VAL_ 2332884828 D2M_DCDC_Enableline_State_28 0 "Disable" 1 "Enable" ;
VAL_ 2332884828 D2M_Communication_State_28 0 "Normal" 1 "CAN lost" ;
VAL_ 2332884828 D2M_DCDC_Sleep_State_28 0 "未休眠" 1 "休眠" ;
VAL_ 2332884829 D2M_DCDC_Work_State_29 0 "Standby" 1 "Normal Run" 2 "Bypass" 3 "Fault" ;
VAL_ 2332884829 D2M_DCDC_AlarmSigl_State_29 0 "No alarm" 1 "Alarm occur（告警信号拉低时）" ;
VAL_ 2332884829 D2M_DCDC_LVPower_State_29 0 "Off" 1 "On" ;
VAL_ 2332884829 D2M_DCDC_Enableline_State_29 0 "Disable" 1 "Enable" ;
VAL_ 2332884829 D2M_Communication_State_29 0 "Normal" 1 "CAN lost" ;
VAL_ 2332884829 D2M_DCDC_Sleep_State_29 0 "未休眠" 1 "休眠" ;
VAL_ 2332884830 D2M_DCDC_Work_State_30 0 "Standby" 1 "Normal Run" 2 "Bypass" 3 "Fault" ;
VAL_ 2332884830 D2M_DCDC_AlarmSigl_State_30 0 "No alarm" 1 "Alarm occur（告警信号拉低时）" ;
VAL_ 2332884830 D2M_DCDC_LVPower_State_30 0 "Off" 1 "On" ;
VAL_ 2332884830 D2M_DCDC_Enableline_State_30 0 "Disable" 1 "Enable" ;
VAL_ 2332884830 D2M_Communication_State_30 0 "Normal" 1 "CAN lost" ;
VAL_ 2332884830 D2M_DCDC_Sleep_State_30 0 "未休眠" 1 "休眠" ;
VAL_ 2332884831 D2M_DCDC_Work_State_31 0 "Standby" 1 "Normal Run" 2 "Bypass" 3 "Fault" ;
VAL_ 2332884831 D2M_DCDC_AlarmSigl_State_31 0 "No alarm" 1 "Alarm occur（告警信号拉低时）" ;
VAL_ 2332884831 D2M_DCDC_LVPower_State_31 0 "Off" 1 "On" ;
VAL_ 2332884831 D2M_DCDC_Enableline_State_31 0 "Disable" 1 "Enable" ;
VAL_ 2332884831 D2M_Communication_State_31 0 "Normal" 1 "CAN lost" ;
VAL_ 2332884831 D2M_DCDC_Sleep_State_31 0 "未休眠" 1 "休眠" ;
VAL_ 2332884832 D2M_DCDC_Work_State_32 0 "Standby" 1 "Normal Run" 2 "Bypass" 3 "Fault" ;
VAL_ 2332884832 D2M_DCDC_AlarmSigl_State_32 0 "No alarm" 1 "Alarm occur（告警信号拉低时）" ;
VAL_ 2332884832 D2M_DCDC_LVPower_State_32 0 "Off" 1 "On" ;
VAL_ 2332884832 D2M_DCDC_Enableline_State_32 0 "Disable" 1 "Enable" ;
VAL_ 2332884832 D2M_Communication_State_32 0 "Normal" 1 "CAN lost" ;
VAL_ 2332884832 D2M_DCDC_Sleep_State_32 0 "未休眠" 1 "休眠" ;
VAL_ 2332884833 D2M_DCDC_Work_State_33 0 "Standby" 1 "Normal Run" 2 "Bypass" 3 "Fault" ;
VAL_ 2332884833 D2M_DCDC_AlarmSigl_State_33 0 "No alarm" 1 "Alarm occur（告警信号拉低时）" ;
VAL_ 2332884833 D2M_DCDC_LVPower_State_33 0 "Off" 1 "On" ;
VAL_ 2332884833 D2M_DCDC_Enableline_State_33 0 "Disable" 1 "Enable" ;
VAL_ 2332884833 D2M_Communication_State_33 0 "Normal" 1 "CAN lost" ;
VAL_ 2332884833 D2M_DCDC_Sleep_State_33 0 "未休眠" 1 "休眠" ;
VAL_ 2332884834 D2M_DCDC_Work_State_34 0 "Standby" 1 "Normal Run" 2 "Bypass" 3 "Fault" ;
VAL_ 2332884834 D2M_DCDC_AlarmSigl_State_34 0 "No alarm" 1 "Alarm occur（告警信号拉低时）" ;
VAL_ 2332884834 D2M_DCDC_LVPower_State_34 0 "Off" 1 "On" ;
VAL_ 2332884834 D2M_DCDC_Enableline_State_34 0 "Disable" 1 "Enable" ;
VAL_ 2332884834 D2M_Communication_State_34 0 "Normal" 1 "CAN lost" ;
VAL_ 2332884834 D2M_DCDC_Sleep_State_34 0 "未休眠" 1 "休眠" ;
VAL_ 2332884835 D2M_DCDC_Work_State_35 0 "Standby" 1 "Normal Run" 2 "Bypass" 3 "Fault" ;
VAL_ 2332884835 D2M_DCDC_AlarmSigl_State_35 0 "No alarm" 1 "Alarm occur（告警信号拉低时）" ;
VAL_ 2332884835 D2M_DCDC_LVPower_State_35 0 "Off" 1 "On" ;
VAL_ 2332884835 D2M_DCDC_Enableline_State_35 0 "Disable" 1 "Enable" ;
VAL_ 2332884835 D2M_Communication_State_35 0 "Normal" 1 "CAN lost" ;
VAL_ 2332884835 D2M_DCDC_Sleep_State_35 0 "未休眠" 1 "休眠" ;
VAL_ 2332884836 D2M_DCDC_Work_State_36 0 "Standby" 1 "Normal Run" 2 "Bypass" 3 "Fault" ;
VAL_ 2332884836 D2M_DCDC_AlarmSigl_State_36 0 "No alarm" 1 "Alarm occur（告警信号拉低时）" ;
VAL_ 2332884836 D2M_DCDC_LVPower_State_36 0 "Off" 1 "On" ;
VAL_ 2332884836 D2M_DCDC_Enableline_State_36 0 "Disable" 1 "Enable" ;
VAL_ 2332884836 D2M_Communication_State_36 0 "Normal" 1 "CAN lost" ;
VAL_ 2332884836 D2M_DCDC_Sleep_State_36 0 "未休眠" 1 "休眠" ;
VAL_ 2332884837 D2M_DCDC_Work_State_37 0 "Standby" 1 "Normal Run" 2 "Bypass" 3 "Fault" ;
VAL_ 2332884837 D2M_DCDC_AlarmSigl_State_37 0 "No alarm" 1 "Alarm occur（告警信号拉低时）" ;
VAL_ 2332884837 D2M_DCDC_LVPower_State_37 0 "Off" 1 "On" ;
VAL_ 2332884837 D2M_DCDC_Enableline_State_37 0 "Disable" 1 "Enable" ;
VAL_ 2332884837 D2M_Communication_State_37 0 "Normal" 1 "CAN lost" ;
VAL_ 2332884837 D2M_DCDC_Sleep_State_37 0 "未休眠" 1 "休眠" ;
VAL_ 2332884838 D2M_DCDC_Work_State_38 0 "Standby" 1 "Normal Run" 2 "Bypass" 3 "Fault" ;
VAL_ 2332884838 D2M_DCDC_AlarmSigl_State_38 0 "No alarm" 1 "Alarm occur（告警信号拉低时）" ;
VAL_ 2332884838 D2M_DCDC_LVPower_State_38 0 "Off" 1 "On" ;
VAL_ 2332884838 D2M_DCDC_Enableline_State_38 0 "Disable" 1 "Enable" ;
VAL_ 2332884838 D2M_Communication_State_38 0 "Normal" 1 "CAN lost" ;
VAL_ 2332884838 D2M_DCDC_Sleep_State_38 0 "未休眠" 1 "休眠" ;
VAL_ 2332884839 D2M_DCDC_Work_State_39 0 "Standby" 1 "Normal Run" 2 "Bypass" 3 "Fault" ;
VAL_ 2332884839 D2M_DCDC_AlarmSigl_State_39 0 "No alarm" 1 "Alarm occur（告警信号拉低时）" ;
VAL_ 2332884839 D2M_DCDC_LVPower_State_39 0 "Off" 1 "On" ;
VAL_ 2332884839 D2M_DCDC_Enableline_State_39 0 "Disable" 1 "Enable" ;
VAL_ 2332884839 D2M_Communication_State_39 0 "Normal" 1 "CAN lost" ;
VAL_ 2332884839 D2M_DCDC_Sleep_State_39 0 "未休眠" 1 "休眠" ;
VAL_ 2332884840 D2M_DCDC_Work_State_40 0 "Standby" 1 "Normal Run" 2 "Bypass" 3 "Fault" ;
VAL_ 2332884840 D2M_DCDC_AlarmSigl_State_40 0 "No alarm" 1 "Alarm occur（告警信号拉低时）" ;
VAL_ 2332884840 D2M_DCDC_LVPower_State_40 0 "Off" 1 "On" ;
VAL_ 2332884840 D2M_DCDC_Enableline_State_40 0 "Disable" 1 "Enable" ;
VAL_ 2332884840 D2M_Communication_State_40 0 "Normal" 1 "CAN lost" ;
VAL_ 2332884840 D2M_DCDC_Sleep_State_40 0 "未休眠" 1 "休眠" ;
VAL_ 2332884841 D2M_DCDC_Work_State_41 0 "Standby" 1 "Normal Run" 2 "Bypass" 3 "Fault" ;
VAL_ 2332884841 D2M_DCDC_AlarmSigl_State_41 0 "No alarm" 1 "Alarm occur（告警信号拉低时）" ;
VAL_ 2332884841 D2M_DCDC_LVPower_State_41 0 "Off" 1 "On" ;
VAL_ 2332884841 D2M_DCDC_Enableline_State_41 0 "Disable" 1 "Enable" ;
VAL_ 2332884841 D2M_Communication_State_41 0 "Normal" 1 "CAN lost" ;
VAL_ 2332884841 D2M_DCDC_Sleep_State_41 0 "未休眠" 1 "休眠" ;
VAL_ 2332884842 D2M_DCDC_Work_State_42 0 "Standby" 1 "Normal Run" 2 "Bypass" 3 "Fault" ;
VAL_ 2332884842 D2M_DCDC_AlarmSigl_State_42 0 "No alarm" 1 "Alarm occur（告警信号拉低时）" ;
VAL_ 2332884842 D2M_DCDC_LVPower_State_42 0 "Off" 1 "On" ;
VAL_ 2332884842 D2M_DCDC_Enableline_State_42 0 "Disable" 1 "Enable" ;
VAL_ 2332884842 D2M_Communication_State_42 0 "Normal" 1 "CAN lost" ;
VAL_ 2332884842 D2M_DCDC_Sleep_State_42 0 "未休眠" 1 "休眠" ;
VAL_ 2332884843 D2M_DCDC_Work_State_43 0 "Standby" 1 "Normal Run" 2 "Bypass" 3 "Fault" ;
VAL_ 2332884843 D2M_DCDC_AlarmSigl_State_43 0 "No alarm" 1 "Alarm occur（告警信号拉低时）" ;
VAL_ 2332884843 D2M_DCDC_LVPower_State_43 0 "Off" 1 "On" ;
VAL_ 2332884843 D2M_DCDC_Enableline_State_43 0 "Disable" 1 "Enable" ;
VAL_ 2332884843 D2M_Communication_State_43 0 "Normal" 1 "CAN lost" ;
VAL_ 2332884843 D2M_DCDC_Sleep_State_43 0 "未休眠" 1 "休眠" ;
VAL_ 2332884844 D2M_DCDC_Work_State_44 0 "Standby" 1 "Normal Run" 2 "Bypass" 3 "Fault" ;
VAL_ 2332884844 D2M_DCDC_AlarmSigl_State_44 0 "No alarm" 1 "Alarm occur（告警信号拉低时）" ;
VAL_ 2332884844 D2M_DCDC_LVPower_State_44 0 "Off" 1 "On" ;
VAL_ 2332884844 D2M_DCDC_Enableline_State_44 0 "Disable" 1 "Enable" ;
VAL_ 2332884844 D2M_Communication_State_44 0 "Normal" 1 "CAN lost" ;
VAL_ 2332884844 D2M_DCDC_Sleep_State_44 0 "未休眠" 1 "休眠" ;
VAL_ 2332884845 D2M_DCDC_Work_State_45 0 "Standby" 1 "Normal Run" 2 "Bypass" 3 "Fault" ;
VAL_ 2332884845 D2M_DCDC_AlarmSigl_State_45 0 "No alarm" 1 "Alarm occur（告警信号拉低时）" ;
VAL_ 2332884845 D2M_DCDC_LVPower_State_45 0 "Off" 1 "On" ;
VAL_ 2332884845 D2M_DCDC_Enableline_State_45 0 "Disable" 1 "Enable" ;
VAL_ 2332884845 D2M_Communication_State_45 0 "Normal" 1 "CAN lost" ;
VAL_ 2332884845 D2M_DCDC_Sleep_State_45 0 "未休眠" 1 "休眠" ;
VAL_ 2332884846 D2M_DCDC_Work_State_46 0 "Standby" 1 "Normal Run" 2 "Bypass" 3 "Fault" ;
VAL_ 2332884846 D2M_DCDC_AlarmSigl_State_46 0 "No alarm" 1 "Alarm occur（告警信号拉低时）" ;
VAL_ 2332884846 D2M_DCDC_LVPower_State_46 0 "Off" 1 "On" ;
VAL_ 2332884846 D2M_DCDC_Enableline_State_46 0 "Disable" 1 "Enable" ;
VAL_ 2332884846 D2M_Communication_State_46 0 "Normal" 1 "CAN lost" ;
VAL_ 2332884846 D2M_DCDC_Sleep_State_46 0 "未休眠" 1 "休眠" ;
VAL_ 2332884847 D2M_DCDC_Work_State_47 0 "Standby" 1 "Normal Run" 2 "Bypass" 3 "Fault" ;
VAL_ 2332884847 D2M_DCDC_AlarmSigl_State_47 0 "No alarm" 1 "Alarm occur（告警信号拉低时）" ;
VAL_ 2332884847 D2M_DCDC_LVPower_State_47 0 "Off" 1 "On" ;
VAL_ 2332884847 D2M_DCDC_Enableline_State_47 0 "Disable" 1 "Enable" ;
VAL_ 2332884847 D2M_Communication_State_47 0 "Normal" 1 "CAN lost" ;
VAL_ 2332884847 D2M_DCDC_Sleep_State_47 0 "未休眠" 1 "休眠" ;
VAL_ 2332884848 D2M_DCDC_Work_State_48 0 "Standby" 1 "Normal Run" 2 "Bypass" 3 "Fault" ;
VAL_ 2332884848 D2M_DCDC_AlarmSigl_State_48 0 "No alarm" 1 "Alarm occur（告警信号拉低时）" ;
VAL_ 2332884848 D2M_DCDC_LVPower_State_48 0 "Off" 1 "On" ;
VAL_ 2332884848 D2M_DCDC_Enableline_State_48 0 "Disable" 1 "Enable" ;
VAL_ 2332884848 D2M_Communication_State_48 0 "Normal" 1 "CAN lost" ;
VAL_ 2332884848 D2M_DCDC_Sleep_State_48 0 "未休眠" 1 "休眠" ;
VAL_ 2332884849 D2M_DCDC_Work_State_49 0 "Standby" 1 "Normal Run" 2 "Bypass" 3 "Fault" ;
VAL_ 2332884849 D2M_DCDC_AlarmSigl_State_49 0 "No alarm" 1 "Alarm occur（告警信号拉低时）" ;
VAL_ 2332884849 D2M_DCDC_LVPower_State_49 0 "Off" 1 "On" ;
VAL_ 2332884849 D2M_DCDC_Enableline_State_49 0 "Disable" 1 "Enable" ;
VAL_ 2332884849 D2M_Communication_State_49 0 "Normal" 1 "CAN lost" ;
VAL_ 2332884849 D2M_DCDC_Sleep_State_49 0 "未休眠" 1 "休眠" ;
VAL_ 2332884850 D2M_DCDC_Work_State_50 0 "Standby" 1 "Normal Run" 2 "Bypass" 3 "Fault" ;
VAL_ 2332884850 D2M_DCDC_AlarmSigl_State_50 0 "No alarm" 1 "Alarm occur（告警信号拉低时）" ;
VAL_ 2332884850 D2M_DCDC_LVPower_State_50 0 "Off" 1 "On" ;
VAL_ 2332884850 D2M_DCDC_Enableline_State_50 0 "Disable" 1 "Enable" ;
VAL_ 2332884850 D2M_Communication_State_50 0 "Normal" 1 "CAN lost" ;
VAL_ 2332884850 D2M_DCDC_Sleep_State_50 0 "未休眠" 1 "休眠" ;
VAL_ 2332884851 D2M_DCDC_Work_State_51 0 "Standby" 1 "Normal Run" 2 "Bypass" 3 "Fault" ;
VAL_ 2332884851 D2M_DCDC_AlarmSigl_State_51 0 "No alarm" 1 "Alarm occur（告警信号拉低时）" ;
VAL_ 2332884851 D2M_DCDC_LVPower_State_51 0 "Off" 1 "On" ;
VAL_ 2332884851 D2M_DCDC_Enableline_State_51 0 "Disable" 1 "Enable" ;
VAL_ 2332884851 D2M_Communication_State_51 0 "Normal" 1 "CAN lost" ;
VAL_ 2332884851 D2M_DCDC_Sleep_State_51 0 "未休眠" 1 "休眠" ;
VAL_ 2332884852 D2M_DCDC_Work_State_52 0 "Standby" 1 "Normal Run" 2 "Bypass" 3 "Fault" ;
VAL_ 2332884852 D2M_DCDC_AlarmSigl_State_52 0 "No alarm" 1 "Alarm occur（告警信号拉低时）" ;
VAL_ 2332884852 D2M_DCDC_LVPower_State_52 0 "Off" 1 "On" ;
VAL_ 2332884852 D2M_DCDC_Enableline_State_52 0 "Disable" 1 "Enable" ;
VAL_ 2332884852 D2M_Communication_State_52 0 "Normal" 1 "CAN lost" ;
VAL_ 2332884852 D2M_DCDC_Sleep_State_52 0 "未休眠" 1 "休眠" ;
VERSION ""

NS_ :

BS_:

BU_: MBMU PC SBMU IMM ETH DCDC LEMS

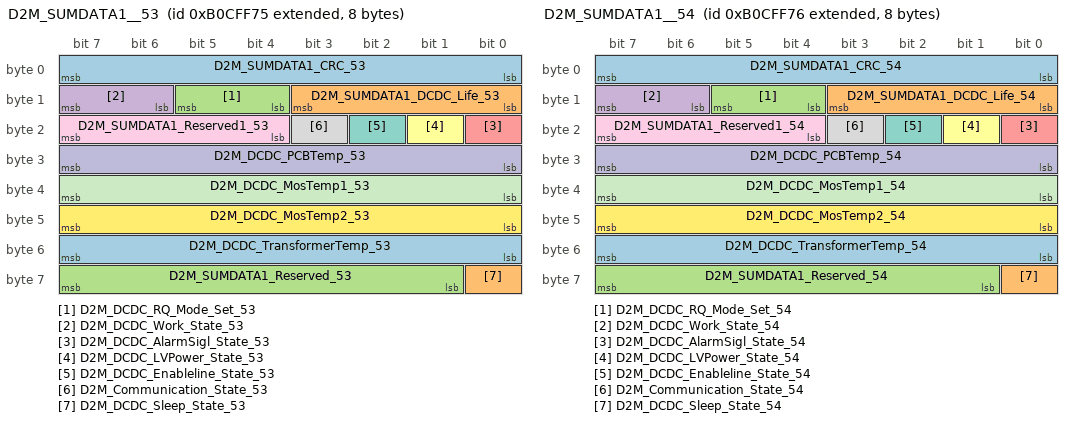
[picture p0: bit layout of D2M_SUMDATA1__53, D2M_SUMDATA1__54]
BO_ 2332884853 D2M_SUMDATA1__53: 8 DCDC
 SG_ D2M_SUMDATA1_CRC_53 : 0|8@1+ (1,0) [0|255] ""  MBMU,PC
 SG_ D2M_SUMDATA1_DCDC_Life_53 : 8|4@1+ (1,0) [0|15] ""  MBMU,PC
 SG_ D2M_DCDC_RQ_Mode_Set_53 : 12|2@1+ (1,0) [0|3] ""  MBMU,PC
 SG_ D2M_DCDC_Work_State_53 : 14|2@1+ (1,0) [0|3] ""  MBMU,PC
 SG_ D2M_DCDC_AlarmSigl_State_53 : 16|1@1+ (1,0) [0|1] ""  MBMU,PC
 SG_ D2M_DCDC_LVPower_State_53 : 17|1@1+ (1,0) [0|1] ""  MBMU,PC
 SG_ D2M_DCDC_Enableline_State_53 : 18|1@1+ (1,0) [0|1] ""  MBMU,PC
 SG_ D2M_Communication_State_53 : 19|1@1+ (1,0) [0|1] ""  MBMU,PC
 SG_ D2M_SUMDATA1_Reserved1_53 : 20|4@1+ (1,0) [0|15] ""  MBMU,PC
 SG_ D2M_DCDC_PCBTemp_53 : 24|8@1+ (1,-40) [-40|215] "℃"  MBMU,PC
 SG_ D2M_DCDC_MosTemp1_53 : 32|8@1+ (1,-40) [-40|215] "℃"  MBMU,PC
 SG_ D2M_DCDC_MosTemp2_53 : 40|8@1+ (1,-40) [-40|215] "℃"  MBMU,PC
 SG_ D2M_DCDC_TransformerTemp_53 : 48|8@1+ (1,-40) [-40|215] "℃"  MBMU,PC
 SG_ D2M_DCDC_Sleep_State_53 : 56|1@1+ (1,0) [0|1] ""  MBMU,PC
 SG_ D2M_SUMDATA1_Reserved_53 : 57|7@1+ (1,0) [0|127] ""  MBMU,PC

BO_ 2332884854 D2M_SUMDATA1__54: 8 DCDC
 SG_ D2M_SUMDATA1_CRC_54 : 0|8@1+ (1,0) [0|255] ""  MBMU,PC
 SG_ D2M_SUMDATA1_DCDC_Life_54 : 8|4@1+ (1,0) [0|15] ""  MBMU,PC
 SG_ D2M_DCDC_RQ_Mode_Set_54 : 12|2@1+ (1,0) [0|3] ""  MBMU,PC
 SG_ D2M_DCDC_Work_State_54 : 14|2@1+ (1,0) [0|3] ""  MBMU,PC
 SG_ D2M_DCDC_AlarmSigl_State_54 : 16|1@1+ (1,0) [0|1] ""  MBMU,PC
 SG_ D2M_DCDC_LVPower_State_54 : 17|1@1+ (1,0) [0|1] ""  MBMU,PC
 SG_ D2M_DCDC_Enableline_State_54 : 18|1@1+ (1,0) [0|1] ""  MBMU,PC
 SG_ D2M_Communication_State_54 : 19|1@1+ (1,0) [0|1] ""  MBMU,PC
 SG_ D2M_SUMDATA1_Reserved1_54 : 20|4@1+ (1,0) [0|15] ""  MBMU,PC
 SG_ D2M_DCDC_PCBTemp_54 : 24|8@1+ (1,-40) [-40|215] "℃"  MBMU,PC
 SG_ D2M_DCDC_MosTemp1_54 : 32|8@1+ (1,-40) [-40|215] "℃"  MBMU,PC
 SG_ D2M_DCDC_MosTemp2_54 : 40|8@1+ (1,-40) [-40|215] "℃"  MBMU,PC
 SG_ D2M_DCDC_TransformerTemp_54 : 48|8@1+ (1,-40) [-40|215] "℃"  MBMU,PC
 SG_ D2M_DCDC_Sleep_State_54 : 56|1@1+ (1,0) [0|1] ""  MBMU,PC
 SG_ D2M_SUMDATA1_Reserved_54 : 57|7@1+ (1,0) [0|127] ""  MBMU,PC

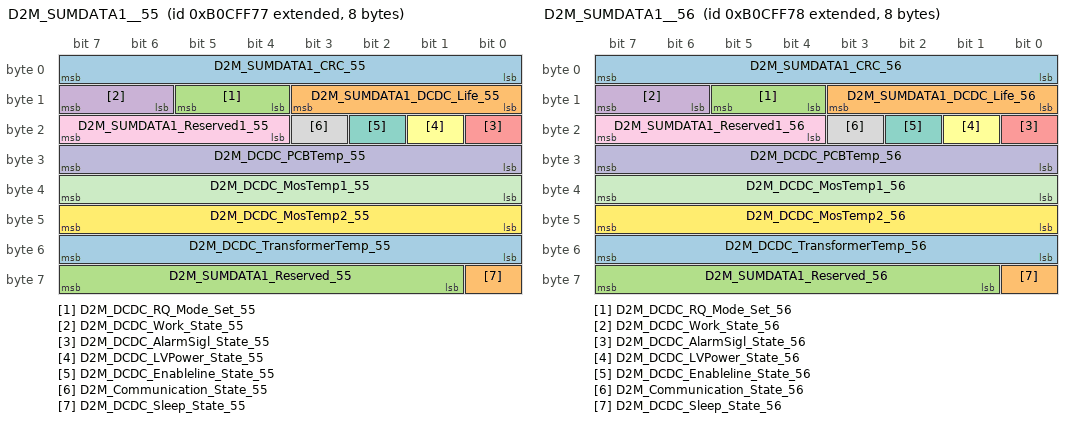
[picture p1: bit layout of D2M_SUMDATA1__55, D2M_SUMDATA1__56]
BO_ 2332884855 D2M_SUMDATA1__55: 8 DCDC
 SG_ D2M_SUMDATA1_CRC_55 : 0|8@1+ (1,0) [0|255] ""  MBMU,PC
 SG_ D2M_SUMDATA1_DCDC_Life_55 : 8|4@1+ (1,0) [0|15] ""  MBMU,PC
 SG_ D2M_DCDC_RQ_Mode_Set_55 : 12|2@1+ (1,0) [0|3] ""  MBMU,PC
 SG_ D2M_DCDC_Work_State_55 : 14|2@1+ (1,0) [0|3] ""  MBMU,PC
 SG_ D2M_DCDC_AlarmSigl_State_55 : 16|1@1+ (1,0) [0|1] ""  MBMU,PC
 SG_ D2M_DCDC_LVPower_State_55 : 17|1@1+ (1,0) [0|1] ""  MBMU,PC
 SG_ D2M_DCDC_Enableline_State_55 : 18|1@1+ (1,0) [0|1] ""  MBMU,PC
 SG_ D2M_Communication_State_55 : 19|1@1+ (1,0) [0|1] ""  MBMU,PC
 SG_ D2M_SUMDATA1_Reserved1_55 : 20|4@1+ (1,0) [0|15] ""  MBMU,PC
 SG_ D2M_DCDC_PCBTemp_55 : 24|8@1+ (1,-40) [-40|215] "℃"  MBMU,PC
 SG_ D2M_DCDC_MosTemp1_55 : 32|8@1+ (1,-40) [-40|215] "℃"  MBMU,PC
 SG_ D2M_DCDC_MosTemp2_55 : 40|8@1+ (1,-40) [-40|215] "℃"  MBMU,PC
 SG_ D2M_DCDC_TransformerTemp_55 : 48|8@1+ (1,-40) [-40|215] "℃"  MBMU,PC
 SG_ D2M_DCDC_Sleep_State_55 : 56|1@1+ (1,0) [0|1] ""  MBMU,PC
 SG_ D2M_SUMDATA1_Reserved_55 : 57|7@1+ (1,0) [0|127] ""  MBMU,PC

BO_ 2332884856 D2M_SUMDATA1__56: 8 DCDC
 SG_ D2M_SUMDATA1_CRC_56 : 0|8@1+ (1,0) [0|255] ""  MBMU,PC
 SG_ D2M_SUMDATA1_DCDC_Life_56 : 8|4@1+ (1,0) [0|15] ""  MBMU,PC
 SG_ D2M_DCDC_RQ_Mode_Set_56 : 12|2@1+ (1,0) [0|3] ""  MBMU,PC
 SG_ D2M_DCDC_Work_State_56 : 14|2@1+ (1,0) [0|3] ""  MBMU,PC
 SG_ D2M_DCDC_AlarmSigl_State_56 : 16|1@1+ (1,0) [0|1] ""  MBMU,PC
 SG_ D2M_DCDC_LVPower_State_56 : 17|1@1+ (1,0) [0|1] ""  MBMU,PC
 SG_ D2M_DCDC_Enableline_State_56 : 18|1@1+ (1,0) [0|1] ""  MBMU,PC
 SG_ D2M_Communication_State_56 : 19|1@1+ (1,0) [0|1] ""  MBMU,PC
 SG_ D2M_SUMDATA1_Reserved1_56 : 20|4@1+ (1,0) [0|15] ""  MBMU,PC
 SG_ D2M_DCDC_PCBTemp_56 : 24|8@1+ (1,-40) [-40|215] "℃"  MBMU,PC
 SG_ D2M_DCDC_MosTemp1_56 : 32|8@1+ (1,-40) [-40|215] "℃"  MBMU,PC
 SG_ D2M_DCDC_MosTemp2_56 : 40|8@1+ (1,-40) [-40|215] "℃"  MBMU,PC
 SG_ D2M_DCDC_TransformerTemp_56 : 48|8@1+ (1,-40) [-40|215] "℃"  MBMU,PC
 SG_ D2M_DCDC_Sleep_State_56 : 56|1@1+ (1,0) [0|1] ""  MBMU,PC
 SG_ D2M_SUMDATA1_Reserved_56 : 57|7@1+ (1,0) [0|127] ""  MBMU,PC

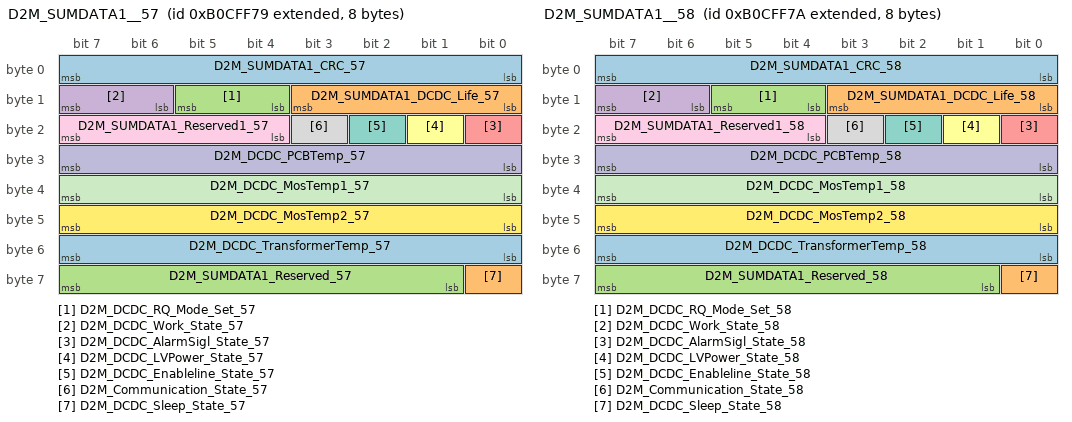
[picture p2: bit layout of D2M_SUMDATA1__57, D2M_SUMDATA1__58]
BO_ 2332884857 D2M_SUMDATA1__57: 8 DCDC
 SG_ D2M_SUMDATA1_CRC_57 : 0|8@1+ (1,0) [0|255] ""  MBMU,PC
 SG_ D2M_SUMDATA1_DCDC_Life_57 : 8|4@1+ (1,0) [0|15] ""  MBMU,PC
 SG_ D2M_DCDC_RQ_Mode_Set_57 : 12|2@1+ (1,0) [0|3] ""  MBMU,PC
 SG_ D2M_DCDC_Work_State_57 : 14|2@1+ (1,0) [0|3] ""  MBMU,PC
 SG_ D2M_DCDC_AlarmSigl_State_57 : 16|1@1+ (1,0) [0|1] ""  MBMU,PC
 SG_ D2M_DCDC_LVPower_State_57 : 17|1@1+ (1,0) [0|1] ""  MBMU,PC
 SG_ D2M_DCDC_Enableline_State_57 : 18|1@1+ (1,0) [0|1] ""  MBMU,PC
 SG_ D2M_Communication_State_57 : 19|1@1+ (1,0) [0|1] ""  MBMU,PC
 SG_ D2M_SUMDATA1_Reserved1_57 : 20|4@1+ (1,0) [0|15] ""  MBMU,PC
 SG_ D2M_DCDC_PCBTemp_57 : 24|8@1+ (1,-40) [-40|215] "℃"  MBMU,PC
 SG_ D2M_DCDC_MosTemp1_57 : 32|8@1+ (1,-40) [-40|215] "℃"  MBMU,PC
 SG_ D2M_DCDC_MosTemp2_57 : 40|8@1+ (1,-40) [-40|215] "℃"  MBMU,PC
 SG_ D2M_DCDC_TransformerTemp_57 : 48|8@1+ (1,-40) [-40|215] "℃"  MBMU,PC
 SG_ D2M_DCDC_Sleep_State_57 : 56|1@1+ (1,0) [0|1] ""  MBMU,PC
 SG_ D2M_SUMDATA1_Reserved_57 : 57|7@1+ (1,0) [0|127] ""  MBMU,PC

BO_ 2332884858 D2M_SUMDATA1__58: 8 DCDC
 SG_ D2M_SUMDATA1_CRC_58 : 0|8@1+ (1,0) [0|255] ""  MBMU,PC
 SG_ D2M_SUMDATA1_DCDC_Life_58 : 8|4@1+ (1,0) [0|15] ""  MBMU,PC
 SG_ D2M_DCDC_RQ_Mode_Set_58 : 12|2@1+ (1,0) [0|3] ""  MBMU,PC
 SG_ D2M_DCDC_Work_State_58 : 14|2@1+ (1,0) [0|3] ""  MBMU,PC
 SG_ D2M_DCDC_AlarmSigl_State_58 : 16|1@1+ (1,0) [0|1] ""  MBMU,PC
 SG_ D2M_DCDC_LVPower_State_58 : 17|1@1+ (1,0) [0|1] ""  MBMU,PC
 SG_ D2M_DCDC_Enableline_State_58 : 18|1@1+ (1,0) [0|1] ""  MBMU,PC
 SG_ D2M_Communication_State_58 : 19|1@1+ (1,0) [0|1] ""  MBMU,PC
 SG_ D2M_SUMDATA1_Reserved1_58 : 20|4@1+ (1,0) [0|15] ""  MBMU,PC
 SG_ D2M_DCDC_PCBTemp_58 : 24|8@1+ (1,-40) [-40|215] "℃"  MBMU,PC
 SG_ D2M_DCDC_MosTemp1_58 : 32|8@1+ (1,-40) [-40|215] "℃"  MBMU,PC
 SG_ D2M_DCDC_MosTemp2_58 : 40|8@1+ (1,-40) [-40|215] "℃"  MBMU,PC
 SG_ D2M_DCDC_TransformerTemp_58 : 48|8@1+ (1,-40) [-40|215] "℃"  MBMU,PC
 SG_ D2M_DCDC_Sleep_State_58 : 56|1@1+ (1,0) [0|1] ""  MBMU,PC
 SG_ D2M_SUMDATA1_Reserved_58 : 57|7@1+ (1,0) [0|127] ""  MBMU,PC

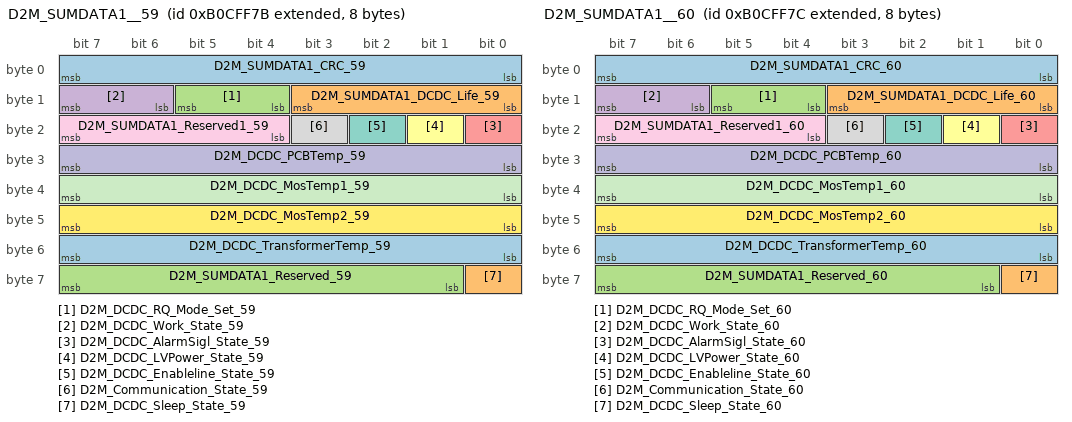
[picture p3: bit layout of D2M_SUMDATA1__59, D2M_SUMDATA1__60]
BO_ 2332884859 D2M_SUMDATA1__59: 8 DCDC
 SG_ D2M_SUMDATA1_CRC_59 : 0|8@1+ (1,0) [0|255] ""  MBMU,PC
 SG_ D2M_SUMDATA1_DCDC_Life_59 : 8|4@1+ (1,0) [0|15] ""  MBMU,PC
 SG_ D2M_DCDC_RQ_Mode_Set_59 : 12|2@1+ (1,0) [0|3] ""  MBMU,PC
 SG_ D2M_DCDC_Work_State_59 : 14|2@1+ (1,0) [0|3] ""  MBMU,PC
 SG_ D2M_DCDC_AlarmSigl_State_59 : 16|1@1+ (1,0) [0|1] ""  MBMU,PC
 SG_ D2M_DCDC_LVPower_State_59 : 17|1@1+ (1,0) [0|1] ""  MBMU,PC
 SG_ D2M_DCDC_Enableline_State_59 : 18|1@1+ (1,0) [0|1] ""  MBMU,PC
 SG_ D2M_Communication_State_59 : 19|1@1+ (1,0) [0|1] ""  MBMU,PC
 SG_ D2M_SUMDATA1_Reserved1_59 : 20|4@1+ (1,0) [0|15] ""  MBMU,PC
 SG_ D2M_DCDC_PCBTemp_59 : 24|8@1+ (1,-40) [-40|215] "℃"  MBMU,PC
 SG_ D2M_DCDC_MosTemp1_59 : 32|8@1+ (1,-40) [-40|215] "℃"  MBMU,PC
 SG_ D2M_DCDC_MosTemp2_59 : 40|8@1+ (1,-40) [-40|215] "℃"  MBMU,PC
 SG_ D2M_DCDC_TransformerTemp_59 : 48|8@1+ (1,-40) [-40|215] "℃"  MBMU,PC
 SG_ D2M_DCDC_Sleep_State_59 : 56|1@1+ (1,0) [0|1] ""  MBMU,PC
 SG_ D2M_SUMDATA1_Reserved_59 : 57|7@1+ (1,0) [0|127] ""  MBMU,PC

BO_ 2332884860 D2M_SUMDATA1__60: 8 DCDC
 SG_ D2M_SUMDATA1_CRC_60 : 0|8@1+ (1,0) [0|255] ""  MBMU,PC
 SG_ D2M_SUMDATA1_DCDC_Life_60 : 8|4@1+ (1,0) [0|15] ""  MBMU,PC
 SG_ D2M_DCDC_RQ_Mode_Set_60 : 12|2@1+ (1,0) [0|3] ""  MBMU,PC
 SG_ D2M_DCDC_Work_State_60 : 14|2@1+ (1,0) [0|3] ""  MBMU,PC
 SG_ D2M_DCDC_AlarmSigl_State_60 : 16|1@1+ (1,0) [0|1] ""  MBMU,PC
 SG_ D2M_DCDC_LVPower_State_60 : 17|1@1+ (1,0) [0|1] ""  MBMU,PC
 SG_ D2M_DCDC_Enableline_State_60 : 18|1@1+ (1,0) [0|1] ""  MBMU,PC
 SG_ D2M_Communication_State_60 : 19|1@1+ (1,0) [0|1] ""  MBMU,PC
 SG_ D2M_SUMDATA1_Reserved1_60 : 20|4@1+ (1,0) [0|15] ""  MBMU,PC
 SG_ D2M_DCDC_PCBTemp_60 : 24|8@1+ (1,-40) [-40|215] "℃"  MBMU,PC
 SG_ D2M_DCDC_MosTemp1_60 : 32|8@1+ (1,-40) [-40|215] "℃"  MBMU,PC
 SG_ D2M_DCDC_MosTemp2_60 : 40|8@1+ (1,-40) [-40|215] "℃"  MBMU,PC
 SG_ D2M_DCDC_TransformerTemp_60 : 48|8@1+ (1,-40) [-40|215] "℃"  MBMU,PC
 SG_ D2M_DCDC_Sleep_State_60 : 56|1@1+ (1,0) [0|1] ""  MBMU,PC
 SG_ D2M_SUMDATA1_Reserved_60 : 57|7@1+ (1,0) [0|127] ""  MBMU,PC

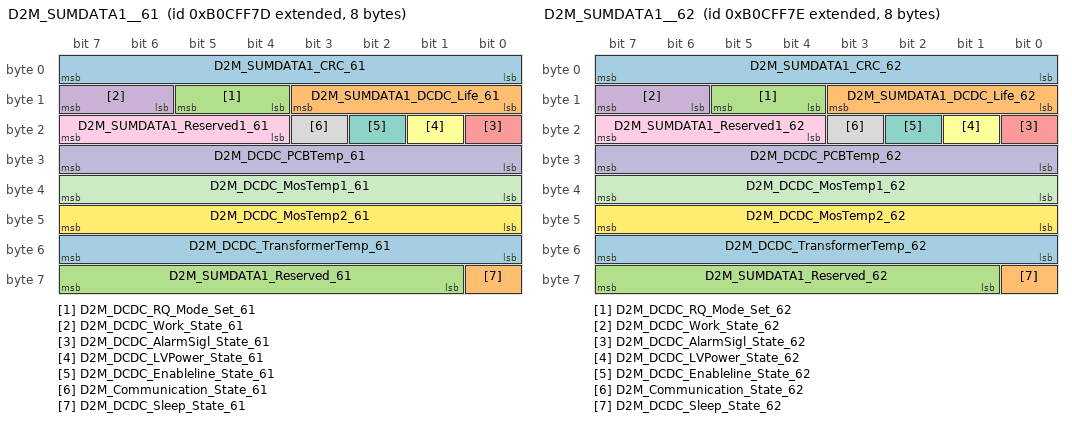
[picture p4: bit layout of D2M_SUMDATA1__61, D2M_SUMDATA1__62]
BO_ 2332884861 D2M_SUMDATA1__61: 8 DCDC
 SG_ D2M_SUMDATA1_CRC_61 : 0|8@1+ (1,0) [0|255] ""  MBMU,PC
 SG_ D2M_SUMDATA1_DCDC_Life_61 : 8|4@1+ (1,0) [0|15] ""  MBMU,PC
 SG_ D2M_DCDC_RQ_Mode_Set_61 : 12|2@1+ (1,0) [0|3] ""  MBMU,PC
 SG_ D2M_DCDC_Work_State_61 : 14|2@1+ (1,0) [0|3] ""  MBMU,PC
 SG_ D2M_DCDC_AlarmSigl_State_61 : 16|1@1+ (1,0) [0|1] ""  MBMU,PC
 SG_ D2M_DCDC_LVPower_State_61 : 17|1@1+ (1,0) [0|1] ""  MBMU,PC
 SG_ D2M_DCDC_Enableline_State_61 : 18|1@1+ (1,0) [0|1] ""  MBMU,PC
 SG_ D2M_Communication_State_61 : 19|1@1+ (1,0) [0|1] ""  MBMU,PC
 SG_ D2M_SUMDATA1_Reserved1_61 : 20|4@1+ (1,0) [0|15] ""  MBMU,PC
 SG_ D2M_DCDC_PCBTemp_61 : 24|8@1+ (1,-40) [-40|215] "℃"  MBMU,PC
 SG_ D2M_DCDC_MosTemp1_61 : 32|8@1+ (1,-40) [-40|215] "℃"  MBMU,PC
 SG_ D2M_DCDC_MosTemp2_61 : 40|8@1+ (1,-40) [-40|215] "℃"  MBMU,PC
 SG_ D2M_DCDC_TransformerTemp_61 : 48|8@1+ (1,-40) [-40|215] "℃"  MBMU,PC
 SG_ D2M_DCDC_Sleep_State_61 : 56|1@1+ (1,0) [0|1] ""  MBMU,PC
 SG_ D2M_SUMDATA1_Reserved_61 : 57|7@1+ (1,0) [0|127] ""  MBMU,PC

BO_ 2332884862 D2M_SUMDATA1__62: 8 DCDC
 SG_ D2M_SUMDATA1_CRC_62 : 0|8@1+ (1,0) [0|255] ""  MBMU,PC
 SG_ D2M_SUMDATA1_DCDC_Life_62 : 8|4@1+ (1,0) [0|15] ""  MBMU,PC
 SG_ D2M_DCDC_RQ_Mode_Set_62 : 12|2@1+ (1,0) [0|3] ""  MBMU,PC
 SG_ D2M_DCDC_Work_State_62 : 14|2@1+ (1,0) [0|3] ""  MBMU,PC
 SG_ D2M_DCDC_AlarmSigl_State_62 : 16|1@1+ (1,0) [0|1] ""  MBMU,PC
 SG_ D2M_DCDC_LVPower_State_62 : 17|1@1+ (1,0) [0|1] ""  MBMU,PC
 SG_ D2M_DCDC_Enableline_State_62 : 18|1@1+ (1,0) [0|1] ""  MBMU,PC
 SG_ D2M_Communication_State_62 : 19|1@1+ (1,0) [0|1] ""  MBMU,PC
 SG_ D2M_SUMDATA1_Reserved1_62 : 20|4@1+ (1,0) [0|15] ""  MBMU,PC
 SG_ D2M_DCDC_PCBTemp_62 : 24|8@1+ (1,-40) [-40|215] "℃"  MBMU,PC
 SG_ D2M_DCDC_MosTemp1_62 : 32|8@1+ (1,-40) [-40|215] "℃"  MBMU,PC
 SG_ D2M_DCDC_MosTemp2_62 : 40|8@1+ (1,-40) [-40|215] "℃"  MBMU,PC
 SG_ D2M_DCDC_TransformerTemp_62 : 48|8@1+ (1,-40) [-40|215] "℃"  MBMU,PC
 SG_ D2M_DCDC_Sleep_State_62 : 56|1@1+ (1,0) [0|1] ""  MBMU,PC
 SG_ D2M_SUMDATA1_Reserved_62 : 57|7@1+ (1,0) [0|127] ""  MBMU,PC

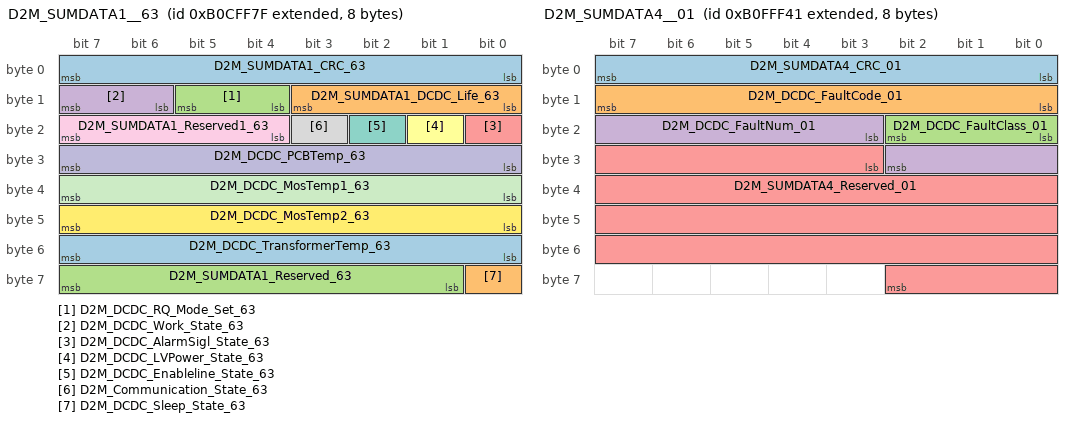
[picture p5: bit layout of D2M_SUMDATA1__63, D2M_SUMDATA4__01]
BO_ 2332884863 D2M_SUMDATA1__63: 8 DCDC
 SG_ D2M_SUMDATA1_CRC_63 : 0|8@1+ (1,0) [0|255] ""  MBMU,PC
 SG_ D2M_SUMDATA1_DCDC_Life_63 : 8|4@1+ (1,0) [0|15] ""  MBMU,PC
 SG_ D2M_DCDC_RQ_Mode_Set_63 : 12|2@1+ (1,0) [0|3] ""  MBMU,PC
 SG_ D2M_DCDC_Work_State_63 : 14|2@1+ (1,0) [0|3] ""  MBMU,PC
 SG_ D2M_DCDC_AlarmSigl_State_63 : 16|1@1+ (1,0) [0|1] ""  MBMU,PC
 SG_ D2M_DCDC_LVPower_State_63 : 17|1@1+ (1,0) [0|1] ""  MBMU,PC
 SG_ D2M_DCDC_Enableline_State_63 : 18|1@1+ (1,0) [0|1] ""  MBMU,PC
 SG_ D2M_Communication_State_63 : 19|1@1+ (1,0) [0|1] ""  MBMU,PC
 SG_ D2M_SUMDATA1_Reserved1_63 : 20|4@1+ (1,0) [0|15] ""  MBMU,PC
 SG_ D2M_DCDC_PCBTemp_63 : 24|8@1+ (1,-40) [-40|215] "℃"  MBMU,PC
 SG_ D2M_DCDC_MosTemp1_63 : 32|8@1+ (1,-40) [-40|215] "℃"  MBMU,PC
 SG_ D2M_DCDC_MosTemp2_63 : 40|8@1+ (1,-40) [-40|215] "℃"  MBMU,PC
 SG_ D2M_DCDC_TransformerTemp_63 : 48|8@1+ (1,-40) [-40|215] "℃"  MBMU,PC
 SG_ D2M_DCDC_Sleep_State_63 : 56|1@1+ (1,0) [0|1] ""  MBMU,PC
 SG_ D2M_SUMDATA1_Reserved_63 : 57|7@1+ (1,0) [0|127] ""  MBMU,PC

BO_ 2332950337 D2M_SUMDATA2__01: 8 DCDC
 SG_ D2M_SUMDATA2_CRC_01 : 0|8@1+ (1,0) [0|255] ""  MBMU,PC
 SG_ D2M_DCDC_Output_Voltage_01 : 8|16@1+ (0.01,-200) [-200|455.35] "V"  MBMU,PC
 SG_ D2M_DCDC_Input_Voltage_01 : 24|16@1+ (0.05,0) [0|3276.75] "V"  MBMU,PC
 SG_ D2M_DCDC_Output_Current_01 : 40|16@1+ (0.05,-2000) [-2000|1276.75] "A"  MBMU,PC
 SG_ D2M_DCDC_Input_Current_01 : 56|8@1+ (0.2,-25) [-25|26] "A"  MBMU,PC

BO_ 2332950338 D2M_SUMDATA2__02: 8 DCDC
 SG_ D2M_SUMDATA2_CRC_02 : 0|8@1+ (1,0) [0|255] ""  MBMU,PC
 SG_ D2M_DCDC_Output_Voltage_02 : 8|16@1+ (0.01,-200) [-200|455.35] "V"  MBMU,PC
 SG_ D2M_DCDC_Input_Voltage_02 : 24|16@1+ (0.05,0) [0|3276.75] "V"  MBMU,PC
 SG_ D2M_DCDC_Output_Current_02 : 40|16@1+ (0.05,-2000) [-2000|1276.75] "A"  MBMU,PC
 SG_ D2M_DCDC_Input_Current_02 : 56|8@1+ (0.2,-25) [-25|26] "A"  MBMU,PC

BO_ 2332950339 D2M_SUMDATA2__03: 8 DCDC
 SG_ D2M_SUMDATA2_CRC_03 : 0|8@1+ (1,0) [0|255] ""  MBMU,PC
 SG_ D2M_DCDC_Output_Voltage_03 : 8|16@1+ (0.01,-200) [-200|455.35] "V"  MBMU,PC
 SG_ D2M_DCDC_Input_Voltage_03 : 24|16@1+ (0.05,0) [0|3276.75] "V"  MBMU,PC
 SG_ D2M_DCDC_Output_Current_03 : 40|16@1+ (0.05,-2000) [-2000|1276.75] "A"  MBMU,PC
 SG_ D2M_DCDC_Input_Current_03 : 56|8@1+ (0.2,-25) [-25|26] "A"  MBMU,PC

BO_ 2332950340 D2M_SUMDATA2__04: 8 DCDC
 SG_ D2M_SUMDATA2_CRC_04 : 0|8@1+ (1,0) [0|255] ""  MBMU,PC
 SG_ D2M_DCDC_Output_Voltage_04 : 8|16@1+ (0.01,-200) [-200|455.35] "V"  MBMU,PC
 SG_ D2M_DCDC_Input_Voltage_04 : 24|16@1+ (0.05,0) [0|3276.75] "V"  MBMU,PC
 SG_ D2M_DCDC_Output_Current_04 : 40|16@1+ (0.05,-2000) [-2000|1276.75] "A"  MBMU,PC
 SG_ D2M_DCDC_Input_Current_04 : 56|8@1+ (0.2,-25) [-25|26] "A"  MBMU,PC

BO_ 2332950341 D2M_SUMDATA2__05: 8 DCDC
 SG_ D2M_SUMDATA2_CRC_05 : 0|8@1+ (1,0) [0|255] ""  MBMU,PC
 SG_ D2M_DCDC_Output_Voltage_05 : 8|16@1+ (0.01,-200) [-200|455.35] "V"  MBMU,PC
 SG_ D2M_DCDC_Input_Voltage_05 : 24|16@1+ (0.05,0) [0|3276.75] "V"  MBMU,PC
 SG_ D2M_DCDC_Output_Current_05 : 40|16@1+ (0.05,-2000) [-2000|1276.75] "A"  MBMU,PC
 SG_ D2M_DCDC_Input_Current_05 : 56|8@1+ (0.2,-25) [-25|26] "A"  MBMU,PC

BO_ 2332950342 D2M_SUMDATA2__06: 8 DCDC
 SG_ D2M_SUMDATA2_CRC_06 : 0|8@1+ (1,0) [0|255] ""  MBMU,PC
 SG_ D2M_DCDC_Output_Voltage_06 : 8|16@1+ (0.01,-200) [-200|455.35] "V"  MBMU,PC
 SG_ D2M_DCDC_Input_Voltage_06 : 24|16@1+ (0.05,0) [0|3276.75] "V"  MBMU,PC
 SG_ D2M_DCDC_Output_Current_06 : 40|16@1+ (0.05,-2000) [-2000|1276.75] "A"  MBMU,PC
 SG_ D2M_DCDC_Input_Current_06 : 56|8@1+ (0.2,-25) [-25|26] "A"  MBMU,PC

BO_ 2332950343 D2M_SUMDATA2__07: 8 DCDC
 SG_ D2M_SUMDATA2_CRC_07 : 0|8@1+ (1,0) [0|255] ""  MBMU,PC
 SG_ D2M_DCDC_Output_Voltage_07 : 8|16@1+ (0.01,-200) [-200|455.35] "V"  MBMU,PC
 SG_ D2M_DCDC_Input_Voltage_07 : 24|16@1+ (0.05,0) [0|3276.75] "V"  MBMU,PC
 SG_ D2M_DCDC_Output_Current_07 : 40|16@1+ (0.05,-2000) [-2000|1276.75] "A"  MBMU,PC
 SG_ D2M_DCDC_Input_Current_07 : 56|8@1+ (0.2,-25) [-25|26] "A"  MBMU,PC

BO_ 2332950344 D2M_SUMDATA2__08: 8 DCDC
 SG_ D2M_SUMDATA2_CRC_08 : 0|8@1+ (1,0) [0|255] ""  MBMU,PC
 SG_ D2M_DCDC_Output_Voltage_08 : 8|16@1+ (0.01,-200) [-200|455.35] "V"  MBMU,PC
 SG_ D2M_DCDC_Input_Voltage_08 : 24|16@1+ (0.05,0) [0|3276.75] "V"  MBMU,PC
 SG_ D2M_DCDC_Output_Current_08 : 40|16@1+ (0.05,-2000) [-2000|1276.75] "A"  MBMU,PC
 SG_ D2M_DCDC_Input_Current_08 : 56|8@1+ (0.2,-25) [-25|26] "A"  MBMU,PC

BO_ 2332950345 D2M_SUMDATA2__09: 8 DCDC
 SG_ D2M_SUMDATA2_CRC_09 : 0|8@1+ (1,0) [0|255] ""  MBMU,PC
 SG_ D2M_DCDC_Output_Voltage_09 : 8|16@1+ (0.01,-200) [-200|455.35] "V"  MBMU,PC
 SG_ D2M_DCDC_Input_Voltage_09 : 24|16@1+ (0.05,0) [0|3276.75] "V"  MBMU,PC
 SG_ D2M_DCDC_Output_Current_09 : 40|16@1+ (0.05,-2000) [-2000|1276.75] "A"  MBMU,PC
 SG_ D2M_DCDC_Input_Current_09 : 56|8@1+ (0.2,-25) [-25|26] "A"  MBMU,PC

BO_ 2332950346 D2M_SUMDATA2__10: 8 DCDC
 SG_ D2M_SUMDATA2_CRC_10 : 0|8@1+ (1,0) [0|255] ""  MBMU,PC
 SG_ D2M_DCDC_Output_Voltage_10 : 8|16@1+ (0.01,-200) [-200|455.35] "V"  MBMU,PC
 SG_ D2M_DCDC_Input_Voltage_10 : 24|16@1+ (0.05,0) [0|3276.75] "V"  MBMU,PC
 SG_ D2M_DCDC_Output_Current_10 : 40|16@1+ (0.05,-2000) [-2000|1276.75] "A"  MBMU,PC
 SG_ D2M_DCDC_Input_Current_10 : 56|8@1+ (0.2,-25) [-25|26] "A"  MBMU,PC

BO_ 2332950347 D2M_SUMDATA2__11: 8 DCDC
 SG_ D2M_SUMDATA2_CRC_11 : 0|8@1+ (1,0) [0|255] ""  MBMU,PC
 SG_ D2M_DCDC_Output_Voltage_11 : 8|16@1+ (0.01,-200) [-200|455.35] "V"  MBMU,PC
 SG_ D2M_DCDC_Input_Voltage_11 : 24|16@1+ (0.05,0) [0|3276.75] "V"  MBMU,PC
 SG_ D2M_DCDC_Output_Current_11 : 40|16@1+ (0.05,-2000) [-2000|1276.75] "A"  MBMU,PC
 SG_ D2M_DCDC_Input_Current_11 : 56|8@1+ (0.2,-25) [-25|26] "A"  MBMU,PC

BO_ 2332950348 D2M_SUMDATA2__12: 8 DCDC
 SG_ D2M_SUMDATA2_CRC_12 : 0|8@1+ (1,0) [0|255] ""  MBMU,PC
 SG_ D2M_DCDC_Output_Voltage_12 : 8|16@1+ (0.01,-200) [-200|455.35] "V"  MBMU,PC
 SG_ D2M_DCDC_Input_Voltage_12 : 24|16@1+ (0.05,0) [0|3276.75] "V"  MBMU,PC
 SG_ D2M_DCDC_Output_Current_12 : 40|16@1+ (0.05,-2000) [-2000|1276.75] "A"  MBMU,PC
 SG_ D2M_DCDC_Input_Current_12 : 56|8@1+ (0.2,-25) [-25|26] "A"  MBMU,PC

BO_ 2332950349 D2M_SUMDATA2__13: 8 DCDC
 SG_ D2M_SUMDATA2_CRC_13 : 0|8@1+ (1,0) [0|255] ""  MBMU,PC
 SG_ D2M_DCDC_Output_Voltage_13 : 8|16@1+ (0.01,-200) [-200|455.35] "V"  MBMU,PC
 SG_ D2M_DCDC_Input_Voltage_13 : 24|16@1+ (0.05,0) [0|3276.75] "V"  MBMU,PC
 SG_ D2M_DCDC_Output_Current_13 : 40|16@1+ (0.05,-2000) [-2000|1276.75] "A"  MBMU,PC
 SG_ D2M_DCDC_Input_Current_13 : 56|8@1+ (0.2,-25) [-25|26] "A"  MBMU,PC

BO_ 2332950350 D2M_SUMDATA2__14: 8 DCDC
 SG_ D2M_SUMDATA2_CRC_14 : 0|8@1+ (1,0) [0|255] ""  MBMU,PC
 SG_ D2M_DCDC_Output_Voltage_14 : 8|16@1+ (0.01,-200) [-200|455.35] "V"  MBMU,PC
 SG_ D2M_DCDC_Input_Voltage_14 : 24|16@1+ (0.05,0) [0|3276.75] "V"  MBMU,PC
 SG_ D2M_DCDC_Output_Current_14 : 40|16@1+ (0.05,-2000) [-2000|1276.75] "A"  MBMU,PC
 SG_ D2M_DCDC_Input_Current_14 : 56|8@1+ (0.2,-25) [-25|26] "A"  MBMU,PC

BO_ 2332950351 D2M_SUMDATA2__15: 8 DCDC
 SG_ D2M_SUMDATA2_CRC_15 : 0|8@1+ (1,0) [0|255] ""  MBMU,PC
 SG_ D2M_DCDC_Output_Voltage_15 : 8|16@1+ (0.01,-200) [-200|455.35] "V"  MBMU,PC
 SG_ D2M_DCDC_Input_Voltage_15 : 24|16@1+ (0.05,0) [0|3276.75] "V"  MBMU,PC
 SG_ D2M_DCDC_Output_Current_15 : 40|16@1+ (0.05,-2000) [-2000|1276.75] "A"  MBMU,PC
 SG_ D2M_DCDC_Input_Current_15 : 56|8@1+ (0.2,-25) [-25|26] "A"  MBMU,PC

BO_ 2332950352 D2M_SUMDATA2__16: 8 DCDC
 SG_ D2M_SUMDATA2_CRC_16 : 0|8@1+ (1,0) [0|255] ""  MBMU,PC
 SG_ D2M_DCDC_Output_Voltage_16 : 8|16@1+ (0.01,-200) [-200|455.35] "V"  MBMU,PC
 SG_ D2M_DCDC_Input_Voltage_16 : 24|16@1+ (0.05,0) [0|3276.75] "V"  MBMU,PC
 SG_ D2M_DCDC_Output_Current_16 : 40|16@1+ (0.05,-2000) [-2000|1276.75] "A"  MBMU,PC
 SG_ D2M_DCDC_Input_Current_16 : 56|8@1+ (0.2,-25) [-25|26] "A"  MBMU,PC

BO_ 2332950353 D2M_SUMDATA2__17: 8 DCDC
 SG_ D2M_SUMDATA2_CRC_17 : 0|8@1+ (1,0) [0|255] ""  MBMU,PC
 SG_ D2M_DCDC_Output_Voltage_17 : 8|16@1+ (0.01,-200) [-200|455.35] "V"  MBMU,PC
 SG_ D2M_DCDC_Input_Voltage_17 : 24|16@1+ (0.05,0) [0|3276.75] "V"  MBMU,PC
 SG_ D2M_DCDC_Output_Current_17 : 40|16@1+ (0.05,-2000) [-2000|1276.75] "A"  MBMU,PC
 SG_ D2M_DCDC_Input_Current_17 : 56|8@1+ (0.2,-25) [-25|26] "A"  MBMU,PC

BO_ 2332950354 D2M_SUMDATA2__18: 8 DCDC
 SG_ D2M_SUMDATA2_CRC_18 : 0|8@1+ (1,0) [0|255] ""  MBMU,PC
 SG_ D2M_DCDC_Output_Voltage_18 : 8|16@1+ (0.01,-200) [-200|455.35] "V"  MBMU,PC
 SG_ D2M_DCDC_Input_Voltage_18 : 24|16@1+ (0.05,0) [0|3276.75] "V"  MBMU,PC
 SG_ D2M_DCDC_Output_Current_18 : 40|16@1+ (0.05,-2000) [-2000|1276.75] "A"  MBMU,PC
 SG_ D2M_DCDC_Input_Current_18 : 56|8@1+ (0.2,-25) [-25|26] "A"  MBMU,PC

BO_ 2332950355 D2M_SUMDATA2__19: 8 DCDC
 SG_ D2M_SUMDATA2_CRC_19 : 0|8@1+ (1,0) [0|255] ""  MBMU,PC
 SG_ D2M_DCDC_Output_Voltage_19 : 8|16@1+ (0.01,-200) [-200|455.35] "V"  MBMU,PC
 SG_ D2M_DCDC_Input_Voltage_19 : 24|16@1+ (0.05,0) [0|3276.75] "V"  MBMU,PC
 SG_ D2M_DCDC_Output_Current_19 : 40|16@1+ (0.05,-2000) [-2000|1276.75] "A"  MBMU,PC
 SG_ D2M_DCDC_Input_Current_19 : 56|8@1+ (0.2,-25) [-25|26] "A"  MBMU,PC

BO_ 2332950356 D2M_SUMDATA2__20: 8 DCDC
 SG_ D2M_SUMDATA2_CRC_20 : 0|8@1+ (1,0) [0|255] ""  MBMU,PC
 SG_ D2M_DCDC_Output_Voltage_20 : 8|16@1+ (0.01,-200) [-200|455.35] "V"  MBMU,PC
 SG_ D2M_DCDC_Input_Voltage_20 : 24|16@1+ (0.05,0) [0|3276.75] "V"  MBMU,PC
 SG_ D2M_DCDC_Output_Current_20 : 40|16@1+ (0.05,-2000) [-2000|1276.75] "A"  MBMU,PC
 SG_ D2M_DCDC_Input_Current_20 : 56|8@1+ (0.2,-25) [-25|26] "A"  MBMU,PC

BO_ 2332950357 D2M_SUMDATA2__21: 8 DCDC
 SG_ D2M_SUMDATA2_CRC_21 : 0|8@1+ (1,0) [0|255] ""  MBMU,PC
 SG_ D2M_DCDC_Output_Voltage_21 : 8|16@1+ (0.01,-200) [-200|455.35] "V"  MBMU,PC
 SG_ D2M_DCDC_Input_Voltage_21 : 24|16@1+ (0.05,0) [0|3276.75] "V"  MBMU,PC
 SG_ D2M_DCDC_Output_Current_21 : 40|16@1+ (0.05,-2000) [-2000|1276.75] "A"  MBMU,PC
 SG_ D2M_DCDC_Input_Current_21 : 56|8@1+ (0.2,-25) [-25|26] "A"  MBMU,PC

BO_ 2332950358 D2M_SUMDATA2__22: 8 DCDC
 SG_ D2M_SUMDATA2_CRC_22 : 0|8@1+ (1,0) [0|255] ""  MBMU,PC
 SG_ D2M_DCDC_Output_Voltage_22 : 8|16@1+ (0.01,-200) [-200|455.35] "V"  MBMU,PC
 SG_ D2M_DCDC_Input_Voltage_22 : 24|16@1+ (0.05,0) [0|3276.75] "V"  MBMU,PC
 SG_ D2M_DCDC_Output_Current_22 : 40|16@1+ (0.05,-2000) [-2000|1276.75] "A"  MBMU,PC
 SG_ D2M_DCDC_Input_Current_22 : 56|8@1+ (0.2,-25) [-25|26] "A"  MBMU,PC

BO_ 2332950359 D2M_SUMDATA2__23: 8 DCDC
 SG_ D2M_SUMDATA2_CRC_23 : 0|8@1+ (1,0) [0|255] ""  MBMU,PC
 SG_ D2M_DCDC_Output_Voltage_23 : 8|16@1+ (0.01,-200) [-200|455.35] "V"  MBMU,PC
 SG_ D2M_DCDC_Input_Voltage_23 : 24|16@1+ (0.05,0) [0|3276.75] "V"  MBMU,PC
 SG_ D2M_DCDC_Output_Current_23 : 40|16@1+ (0.05,-2000) [-2000|1276.75] "A"  MBMU,PC
 SG_ D2M_DCDC_Input_Current_23 : 56|8@1+ (0.2,-25) [-25|26] "A"  MBMU,PC

BO_ 2332950360 D2M_SUMDATA2__24: 8 DCDC
 SG_ D2M_SUMDATA2_CRC_24 : 0|8@1+ (1,0) [0|255] ""  MBMU,PC
 SG_ D2M_DCDC_Output_Voltage_24 : 8|16@1+ (0.01,-200) [-200|455.35] "V"  MBMU,PC
 SG_ D2M_DCDC_Input_Voltage_24 : 24|16@1+ (0.05,0) [0|3276.75] "V"  MBMU,PC
 SG_ D2M_DCDC_Output_Current_24 : 40|16@1+ (0.05,-2000) [-2000|1276.75] "A"  MBMU,PC
 SG_ D2M_DCDC_Input_Current_24 : 56|8@1+ (0.2,-25) [-25|26] "A"  MBMU,PC

BO_ 2332950361 D2M_SUMDATA2__25: 8 DCDC
 SG_ D2M_SUMDATA2_CRC_25 : 0|8@1+ (1,0) [0|255] ""  MBMU,PC
 SG_ D2M_DCDC_Output_Voltage_25 : 8|16@1+ (0.01,-200) [-200|455.35] "V"  MBMU,PC
 SG_ D2M_DCDC_Input_Voltage_25 : 24|16@1+ (0.05,0) [0|3276.75] "V"  MBMU,PC
 SG_ D2M_DCDC_Output_Current_25 : 40|16@1+ (0.05,-2000) [-2000|1276.75] "A"  MBMU,PC
 SG_ D2M_DCDC_Input_Current_25 : 56|8@1+ (0.2,-25) [-25|26] "A"  MBMU,PC

BO_ 2332950362 D2M_SUMDATA2__26: 8 DCDC
 SG_ D2M_SUMDATA2_CRC_26 : 0|8@1+ (1,0) [0|255] ""  MBMU,PC
 SG_ D2M_DCDC_Output_Voltage_26 : 8|16@1+ (0.01,-200) [-200|455.35] "V"  MBMU,PC
 SG_ D2M_DCDC_Input_Voltage_26 : 24|16@1+ (0.05,0) [0|3276.75] "V"  MBMU,PC
 SG_ D2M_DCDC_Output_Current_26 : 40|16@1+ (0.05,-2000) [-2000|1276.75] "A"  MBMU,PC
 SG_ D2M_DCDC_Input_Current_26 : 56|8@1+ (0.2,-25) [-25|26] "A"  MBMU,PC

BO_ 2332950363 D2M_SUMDATA2__27: 8 DCDC
 SG_ D2M_SUMDATA2_CRC_27 : 0|8@1+ (1,0) [0|255] ""  MBMU,PC
 SG_ D2M_DCDC_Output_Voltage_27 : 8|16@1+ (0.01,-200) [-200|455.35] "V"  MBMU,PC
 SG_ D2M_DCDC_Input_Voltage_27 : 24|16@1+ (0.05,0) [0|3276.75] "V"  MBMU,PC
 SG_ D2M_DCDC_Output_Current_27 : 40|16@1+ (0.05,-2000) [-2000|1276.75] "A"  MBMU,PC
 SG_ D2M_DCDC_Input_Current_27 : 56|8@1+ (0.2,-25) [-25|26] "A"  MBMU,PC

BO_ 2332950364 D2M_SUMDATA2__28: 8 DCDC
 SG_ D2M_SUMDATA2_CRC_28 : 0|8@1+ (1,0) [0|255] ""  MBMU,PC
 SG_ D2M_DCDC_Output_Voltage_28 : 8|16@1+ (0.01,-200) [-200|455.35] "V"  MBMU,PC
 SG_ D2M_DCDC_Input_Voltage_28 : 24|16@1+ (0.05,0) [0|3276.75] "V"  MBMU,PC
 SG_ D2M_DCDC_Output_Current_28 : 40|16@1+ (0.05,-2000) [-2000|1276.75] "A"  MBMU,PC
 SG_ D2M_DCDC_Input_Current_28 : 56|8@1+ (0.2,-25) [-25|26] "A"  MBMU,PC

BO_ 2332950365 D2M_SUMDATA2__29: 8 DCDC
 SG_ D2M_SUMDATA2_CRC_29 : 0|8@1+ (1,0) [0|255] ""  MBMU,PC
 SG_ D2M_DCDC_Output_Voltage_29 : 8|16@1+ (0.01,-200) [-200|455.35] "V"  MBMU,PC
 SG_ D2M_DCDC_Input_Voltage_29 : 24|16@1+ (0.05,0) [0|3276.75] "V"  MBMU,PC
 SG_ D2M_DCDC_Output_Current_29 : 40|16@1+ (0.05,-2000) [-2000|1276.75] "A"  MBMU,PC
 SG_ D2M_DCDC_Input_Current_29 : 56|8@1+ (0.2,-25) [-25|26] "A"  MBMU,PC

BO_ 2332950366 D2M_SUMDATA2__30: 8 DCDC
 SG_ D2M_SUMDATA2_CRC_30 : 0|8@1+ (1,0) [0|255] ""  MBMU,PC
 SG_ D2M_DCDC_Output_Voltage_30 : 8|16@1+ (0.01,-200) [-200|455.35] "V"  MBMU,PC
 SG_ D2M_DCDC_Input_Voltage_30 : 24|16@1+ (0.05,0) [0|3276.75] "V"  MBMU,PC
 SG_ D2M_DCDC_Output_Current_30 : 40|16@1+ (0.05,-2000) [-2000|1276.75] "A"  MBMU,PC
 SG_ D2M_DCDC_Input_Current_30 : 56|8@1+ (0.2,-25) [-25|26] "A"  MBMU,PC

BO_ 2332950367 D2M_SUMDATA2__31: 8 DCDC
 SG_ D2M_SUMDATA2_CRC_31 : 0|8@1+ (1,0) [0|255] ""  MBMU,PC
 SG_ D2M_DCDC_Output_Voltage_31 : 8|16@1+ (0.01,-200) [-200|455.35] "V"  MBMU,PC
 SG_ D2M_DCDC_Input_Voltage_31 : 24|16@1+ (0.05,0) [0|3276.75] "V"  MBMU,PC
 SG_ D2M_DCDC_Output_Current_31 : 40|16@1+ (0.05,-2000) [-2000|1276.75] "A"  MBMU,PC
 SG_ D2M_DCDC_Input_Current_31 : 56|8@1+ (0.2,-25) [-25|26] "A"  MBMU,PC

BO_ 2332950368 D2M_SUMDATA2__32: 8 DCDC
 SG_ D2M_SUMDATA2_CRC_32 : 0|8@1+ (1,0) [0|255] ""  MBMU,PC
 SG_ D2M_DCDC_Output_Voltage_32 : 8|16@1+ (0.01,-200) [-200|455.35] "V"  MBMU,PC
 SG_ D2M_DCDC_Input_Voltage_32 : 24|16@1+ (0.05,0) [0|3276.75] "V"  MBMU,PC
 SG_ D2M_DCDC_Output_Current_32 : 40|16@1+ (0.05,-2000) [-2000|1276.75] "A"  MBMU,PC
 SG_ D2M_DCDC_Input_Current_32 : 56|8@1+ (0.2,-25) [-25|26] "A"  MBMU,PC

BO_ 2332950369 D2M_SUMDATA2__33: 8 DCDC
 SG_ D2M_SUMDATA2_CRC_33 : 0|8@1+ (1,0) [0|255] ""  MBMU,PC
 SG_ D2M_DCDC_Output_Voltage_33 : 8|16@1+ (0.01,-200) [-200|455.35] "V"  MBMU,PC
 SG_ D2M_DCDC_Input_Voltage_33 : 24|16@1+ (0.05,0) [0|3276.75] "V"  MBMU,PC
 SG_ D2M_DCDC_Output_Current_33 : 40|16@1+ (0.05,-2000) [-2000|1276.75] "A"  MBMU,PC
 SG_ D2M_DCDC_Input_Current_33 : 56|8@1+ (0.2,-25) [-25|26] "A"  MBMU,PC

BO_ 2332950370 D2M_SUMDATA2__34: 8 DCDC
 SG_ D2M_SUMDATA2_CRC_34 : 0|8@1+ (1,0) [0|255] ""  MBMU,PC
 SG_ D2M_DCDC_Output_Voltage_34 : 8|16@1+ (0.01,-200) [-200|455.35] "V"  MBMU,PC
 SG_ D2M_DCDC_Input_Voltage_34 : 24|16@1+ (0.05,0) [0|3276.75] "V"  MBMU,PC
 SG_ D2M_DCDC_Output_Current_34 : 40|16@1+ (0.05,-2000) [-2000|1276.75] "A"  MBMU,PC
 SG_ D2M_DCDC_Input_Current_34 : 56|8@1+ (0.2,-25) [-25|26] "A"  MBMU,PC

BO_ 2332950371 D2M_SUMDATA2__35: 8 DCDC
 SG_ D2M_SUMDATA2_CRC_35 : 0|8@1+ (1,0) [0|255] ""  MBMU,PC
 SG_ D2M_DCDC_Output_Voltage_35 : 8|16@1+ (0.01,-200) [-200|455.35] "V"  MBMU,PC
 SG_ D2M_DCDC_Input_Voltage_35 : 24|16@1+ (0.05,0) [0|3276.75] "V"  MBMU,PC
 SG_ D2M_DCDC_Output_Current_35 : 40|16@1+ (0.05,-2000) [-2000|1276.75] "A"  MBMU,PC
 SG_ D2M_DCDC_Input_Current_35 : 56|8@1+ (0.2,-25) [-25|26] "A"  MBMU,PC

BO_ 2332950372 D2M_SUMDATA2__36: 8 DCDC
 SG_ D2M_SUMDATA2_CRC_36 : 0|8@1+ (1,0) [0|255] ""  MBMU,PC
 SG_ D2M_DCDC_Output_Voltage_36 : 8|16@1+ (0.01,-200) [-200|455.35] "V"  MBMU,PC
 SG_ D2M_DCDC_Input_Voltage_36 : 24|16@1+ (0.05,0) [0|3276.75] "V"  MBMU,PC
 SG_ D2M_DCDC_Output_Current_36 : 40|16@1+ (0.05,-2000) [-2000|1276.75] "A"  MBMU,PC
 SG_ D2M_DCDC_Input_Current_36 : 56|8@1+ (0.2,-25) [-25|26] "A"  MBMU,PC

BO_ 2332950373 D2M_SUMDATA2__37: 8 DCDC
 SG_ D2M_SUMDATA2_CRC_37 : 0|8@1+ (1,0) [0|255] ""  MBMU,PC
 SG_ D2M_DCDC_Output_Voltage_37 : 8|16@1+ (0.01,-200) [-200|455.35] "V"  MBMU,PC
 SG_ D2M_DCDC_Input_Voltage_37 : 24|16@1+ (0.05,0) [0|3276.75] "V"  MBMU,PC
 SG_ D2M_DCDC_Output_Current_37 : 40|16@1+ (0.05,-2000) [-2000|1276.75] "A"  MBMU,PC
 SG_ D2M_DCDC_Input_Current_37 : 56|8@1+ (0.2,-25) [-25|26] "A"  MBMU,PC

BO_ 2332950374 D2M_SUMDATA2__38: 8 DCDC
 SG_ D2M_SUMDATA2_CRC_38 : 0|8@1+ (1,0) [0|255] ""  MBMU,PC
 SG_ D2M_DCDC_Output_Voltage_38 : 8|16@1+ (0.01,-200) [-200|455.35] "V"  MBMU,PC
 SG_ D2M_DCDC_Input_Voltage_38 : 24|16@1+ (0.05,0) [0|3276.75] "V"  MBMU,PC
 SG_ D2M_DCDC_Output_Current_38 : 40|16@1+ (0.05,-2000) [-2000|1276.75] "A"  MBMU,PC
 SG_ D2M_DCDC_Input_Current_38 : 56|8@1+ (0.2,-25) [-25|26] "A"  MBMU,PC

BO_ 2332950375 D2M_SUMDATA2__39: 8 DCDC
 SG_ D2M_SUMDATA2_CRC_39 : 0|8@1+ (1,0) [0|255] ""  MBMU,PC
 SG_ D2M_DCDC_Output_Voltage_39 : 8|16@1+ (0.01,-200) [-200|455.35] "V"  MBMU,PC
 SG_ D2M_DCDC_Input_Voltage_39 : 24|16@1+ (0.05,0) [0|3276.75] "V"  MBMU,PC
 SG_ D2M_DCDC_Output_Current_39 : 40|16@1+ (0.05,-2000) [-2000|1276.75] "A"  MBMU,PC
 SG_ D2M_DCDC_Input_Current_39 : 56|8@1+ (0.2,-25) [-25|26] "A"  MBMU,PC

BO_ 2332950376 D2M_SUMDATA2__40: 8 DCDC
 SG_ D2M_SUMDATA2_CRC_40 : 0|8@1+ (1,0) [0|255] ""  MBMU,PC
 SG_ D2M_DCDC_Output_Voltage_40 : 8|16@1+ (0.01,-200) [-200|455.35] "V"  MBMU,PC
 SG_ D2M_DCDC_Input_Voltage_40 : 24|16@1+ (0.05,0) [0|3276.75] "V"  MBMU,PC
 SG_ D2M_DCDC_Output_Current_40 : 40|16@1+ (0.05,-2000) [-2000|1276.75] "A"  MBMU,PC
 SG_ D2M_DCDC_Input_Current_40 : 56|8@1+ (0.2,-25) [-25|26] "A"  MBMU,PC

BO_ 2332950377 D2M_SUMDATA2__41: 8 DCDC
 SG_ D2M_SUMDATA2_CRC_41 : 0|8@1+ (1,0) [0|255] ""  MBMU,PC
 SG_ D2M_DCDC_Output_Voltage_41 : 8|16@1+ (0.01,-200) [-200|455.35] "V"  MBMU,PC
 SG_ D2M_DCDC_Input_Voltage_41 : 24|16@1+ (0.05,0) [0|3276.75] "V"  MBMU,PC
 SG_ D2M_DCDC_Output_Current_41 : 40|16@1+ (0.05,-2000) [-2000|1276.75] "A"  MBMU,PC
 SG_ D2M_DCDC_Input_Current_41 : 56|8@1+ (0.2,-25) [-25|26] "A"  MBMU,PC

BO_ 2332950378 D2M_SUMDATA2__42: 8 DCDC
 SG_ D2M_SUMDATA2_CRC_42 : 0|8@1+ (1,0) [0|255] ""  MBMU,PC
 SG_ D2M_DCDC_Output_Voltage_42 : 8|16@1+ (0.01,-200) [-200|455.35] "V"  MBMU,PC
 SG_ D2M_DCDC_Input_Voltage_42 : 24|16@1+ (0.05,0) [0|3276.75] "V"  MBMU,PC
 SG_ D2M_DCDC_Output_Current_42 : 40|16@1+ (0.05,-2000) [-2000|1276.75] "A"  MBMU,PC
 SG_ D2M_DCDC_Input_Current_42 : 56|8@1+ (0.2,-25) [-25|26] "A"  MBMU,PC

BO_ 2332950379 D2M_SUMDATA2__43: 8 DCDC
 SG_ D2M_SUMDATA2_CRC_43 : 0|8@1+ (1,0) [0|255] ""  MBMU,PC
 SG_ D2M_DCDC_Output_Voltage_43 : 8|16@1+ (0.01,-200) [-200|455.35] "V"  MBMU,PC
 SG_ D2M_DCDC_Input_Voltage_43 : 24|16@1+ (0.05,0) [0|3276.75] "V"  MBMU,PC
 SG_ D2M_DCDC_Output_Current_43 : 40|16@1+ (0.05,-2000) [-2000|1276.75] "A"  MBMU,PC
 SG_ D2M_DCDC_Input_Current_43 : 56|8@1+ (0.2,-25) [-25|26] "A"  MBMU,PC

BO_ 2332950380 D2M_SUMDATA2__44: 8 DCDC
 SG_ D2M_SUMDATA2_CRC_44 : 0|8@1+ (1,0) [0|255] ""  MBMU,PC
 SG_ D2M_DCDC_Output_Voltage_44 : 8|16@1+ (0.01,-200) [-200|455.35] "V"  MBMU,PC
 SG_ D2M_DCDC_Input_Voltage_44 : 24|16@1+ (0.05,0) [0|3276.75] "V"  MBMU,PC
 SG_ D2M_DCDC_Output_Current_44 : 40|16@1+ (0.05,-2000) [-2000|1276.75] "A"  MBMU,PC
 SG_ D2M_DCDC_Input_Current_44 : 56|8@1+ (0.2,-25) [-25|26] "A"  MBMU,PC

BO_ 2332950381 D2M_SUMDATA2__45: 8 DCDC
 SG_ D2M_SUMDATA2_CRC_45 : 0|8@1+ (1,0) [0|255] ""  MBMU,PC
 SG_ D2M_DCDC_Output_Voltage_45 : 8|16@1+ (0.01,-200) [-200|455.35] "V"  MBMU,PC
 SG_ D2M_DCDC_Input_Voltage_45 : 24|16@1+ (0.05,0) [0|3276.75] "V"  MBMU,PC
 SG_ D2M_DCDC_Output_Current_45 : 40|16@1+ (0.05,-2000) [-2000|1276.75] "A"  MBMU,PC
 SG_ D2M_DCDC_Input_Current_45 : 56|8@1+ (0.2,-25) [-25|26] "A"  MBMU,PC

BO_ 2332950382 D2M_SUMDATA2__46: 8 DCDC
 SG_ D2M_SUMDATA2_CRC_46 : 0|8@1+ (1,0) [0|255] ""  MBMU,PC
 SG_ D2M_DCDC_Output_Voltage_46 : 8|16@1+ (0.01,-200) [-200|455.35] "V"  MBMU,PC
 SG_ D2M_DCDC_Input_Voltage_46 : 24|16@1+ (0.05,0) [0|3276.75] "V"  MBMU,PC
 SG_ D2M_DCDC_Output_Current_46 : 40|16@1+ (0.05,-2000) [-2000|1276.75] "A"  MBMU,PC
 SG_ D2M_DCDC_Input_Current_46 : 56|8@1+ (0.2,-25) [-25|26] "A"  MBMU,PC

BO_ 2332950383 D2M_SUMDATA2__47: 8 DCDC
 SG_ D2M_SUMDATA2_CRC_47 : 0|8@1+ (1,0) [0|255] ""  MBMU,PC
 SG_ D2M_DCDC_Output_Voltage_47 : 8|16@1+ (0.01,-200) [-200|455.35] "V"  MBMU,PC
 SG_ D2M_DCDC_Input_Voltage_47 : 24|16@1+ (0.05,0) [0|3276.75] "V"  MBMU,PC
 SG_ D2M_DCDC_Output_Current_47 : 40|16@1+ (0.05,-2000) [-2000|1276.75] "A"  MBMU,PC
 SG_ D2M_DCDC_Input_Current_47 : 56|8@1+ (0.2,-25) [-25|26] "A"  MBMU,PC

BO_ 2332950384 D2M_SUMDATA2__48: 8 DCDC
 SG_ D2M_SUMDATA2_CRC_48 : 0|8@1+ (1,0) [0|255] ""  MBMU,PC
 SG_ D2M_DCDC_Output_Voltage_48 : 8|16@1+ (0.01,-200) [-200|455.35] "V"  MBMU,PC
 SG_ D2M_DCDC_Input_Voltage_48 : 24|16@1+ (0.05,0) [0|3276.75] "V"  MBMU,PC
 SG_ D2M_DCDC_Output_Current_48 : 40|16@1+ (0.05,-2000) [-2000|1276.75] "A"  MBMU,PC
 SG_ D2M_DCDC_Input_Current_48 : 56|8@1+ (0.2,-25) [-25|26] "A"  MBMU,PC

BO_ 2332950385 D2M_SUMDATA2__49: 8 DCDC
 SG_ D2M_SUMDATA2_CRC_49 : 0|8@1+ (1,0) [0|255] ""  MBMU,PC
 SG_ D2M_DCDC_Output_Voltage_49 : 8|16@1+ (0.01,-200) [-200|455.35] "V"  MBMU,PC
 SG_ D2M_DCDC_Input_Voltage_49 : 24|16@1+ (0.05,0) [0|3276.75] "V"  MBMU,PC
 SG_ D2M_DCDC_Output_Current_49 : 40|16@1+ (0.05,-2000) [-2000|1276.75] "A"  MBMU,PC
 SG_ D2M_DCDC_Input_Current_49 : 56|8@1+ (0.2,-25) [-25|26] "A"  MBMU,PC

BO_ 2332950386 D2M_SUMDATA2__50: 8 DCDC
 SG_ D2M_SUMDATA2_CRC_50 : 0|8@1+ (1,0) [0|255] ""  MBMU,PC
 SG_ D2M_DCDC_Output_Voltage_50 : 8|16@1+ (0.01,-200) [-200|455.35] "V"  MBMU,PC
 SG_ D2M_DCDC_Input_Voltage_50 : 24|16@1+ (0.05,0) [0|3276.75] "V"  MBMU,PC
 SG_ D2M_DCDC_Output_Current_50 : 40|16@1+ (0.05,-2000) [-2000|1276.75] "A"  MBMU,PC
 SG_ D2M_DCDC_Input_Current_50 : 56|8@1+ (0.2,-25) [-25|26] "A"  MBMU,PC

BO_ 2332950387 D2M_SUMDATA2__51: 8 DCDC
 SG_ D2M_SUMDATA2_CRC_51 : 0|8@1+ (1,0) [0|255] ""  MBMU,PC
 SG_ D2M_DCDC_Output_Voltage_51 : 8|16@1+ (0.01,-200) [-200|455.35] "V"  MBMU,PC
 SG_ D2M_DCDC_Input_Voltage_51 : 24|16@1+ (0.05,0) [0|3276.75] "V"  MBMU,PC
 SG_ D2M_DCDC_Output_Current_51 : 40|16@1+ (0.05,-2000) [-2000|1276.75] "A"  MBMU,PC
 SG_ D2M_DCDC_Input_Current_51 : 56|8@1+ (0.2,-25) [-25|26] "A"  MBMU,PC

BO_ 2332950388 D2M_SUMDATA2__52: 8 DCDC
 SG_ D2M_SUMDATA2_CRC_52 : 0|8@1+ (1,0) [0|255] ""  MBMU,PC
 SG_ D2M_DCDC_Output_Voltage_52 : 8|16@1+ (0.01,-200) [-200|455.35] "V"  MBMU,PC
 SG_ D2M_DCDC_Input_Voltage_52 : 24|16@1+ (0.05,0) [0|3276.75] "V"  MBMU,PC
 SG_ D2M_DCDC_Output_Current_52 : 40|16@1+ (0.05,-2000) [-2000|1276.75] "A"  MBMU,PC
 SG_ D2M_DCDC_Input_Current_52 : 56|8@1+ (0.2,-25) [-25|26] "A"  MBMU,PC

BO_ 2332950389 D2M_SUMDATA2__53: 8 DCDC
 SG_ D2M_SUMDATA2_CRC_53 : 0|8@1+ (1,0) [0|255] ""  MBMU,PC
 SG_ D2M_DCDC_Output_Voltage_53 : 8|16@1+ (0.01,-200) [-200|455.35] "V"  MBMU,PC
 SG_ D2M_DCDC_Input_Voltage_53 : 24|16@1+ (0.05,0) [0|3276.75] "V"  MBMU,PC
 SG_ D2M_DCDC_Output_Current_53 : 40|16@1+ (0.05,-2000) [-2000|1276.75] "A"  MBMU,PC
 SG_ D2M_DCDC_Input_Current_53 : 56|8@1+ (0.2,-25) [-25|26] "A"  MBMU,PC

BO_ 2332950390 D2M_SUMDATA2__54: 8 DCDC
 SG_ D2M_SUMDATA2_CRC_54 : 0|8@1+ (1,0) [0|255] ""  MBMU,PC
 SG_ D2M_DCDC_Output_Voltage_54 : 8|16@1+ (0.01,-200) [-200|455.35] "V"  MBMU,PC
 SG_ D2M_DCDC_Input_Voltage_54 : 24|16@1+ (0.05,0) [0|3276.75] "V"  MBMU,PC
 SG_ D2M_DCDC_Output_Current_54 : 40|16@1+ (0.05,-2000) [-2000|1276.75] "A"  MBMU,PC
 SG_ D2M_DCDC_Input_Current_54 : 56|8@1+ (0.2,-25) [-25|26] "A"  MBMU,PC

BO_ 2332950391 D2M_SUMDATA2__55: 8 DCDC
 SG_ D2M_SUMDATA2_CRC_55 : 0|8@1+ (1,0) [0|255] ""  MBMU,PC
 SG_ D2M_DCDC_Output_Voltage_55 : 8|16@1+ (0.01,-200) [-200|455.35] "V"  MBMU,PC
 SG_ D2M_DCDC_Input_Voltage_55 : 24|16@1+ (0.05,0) [0|3276.75] "V"  MBMU,PC
 SG_ D2M_DCDC_Output_Current_55 : 40|16@1+ (0.05,-2000) [-2000|1276.75] "A"  MBMU,PC
 SG_ D2M_DCDC_Input_Current_55 : 56|8@1+ (0.2,-25) [-25|26] "A"  MBMU,PC

BO_ 2332950392 D2M_SUMDATA2__56: 8 DCDC
 SG_ D2M_SUMDATA2_CRC_56 : 0|8@1+ (1,0) [0|255] ""  MBMU,PC
 SG_ D2M_DCDC_Output_Voltage_56 : 8|16@1+ (0.01,-200) [-200|455.35] "V"  MBMU,PC
 SG_ D2M_DCDC_Input_Voltage_56 : 24|16@1+ (0.05,0) [0|3276.75] "V"  MBMU,PC
 SG_ D2M_DCDC_Output_Current_56 : 40|16@1+ (0.05,-2000) [-2000|1276.75] "A"  MBMU,PC
 SG_ D2M_DCDC_Input_Current_56 : 56|8@1+ (0.2,-25) [-25|26] "A"  MBMU,PC

BO_ 2332950393 D2M_SUMDATA2__57: 8 DCDC
 SG_ D2M_SUMDATA2_CRC_57 : 0|8@1+ (1,0) [0|255] ""  MBMU,PC
 SG_ D2M_DCDC_Output_Voltage_57 : 8|16@1+ (0.01,-200) [-200|455.35] "V"  MBMU,PC
 SG_ D2M_DCDC_Input_Voltage_57 : 24|16@1+ (0.05,0) [0|3276.75] "V"  MBMU,PC
 SG_ D2M_DCDC_Output_Current_57 : 40|16@1+ (0.05,-2000) [-2000|1276.75] "A"  MBMU,PC
 SG_ D2M_DCDC_Input_Current_57 : 56|8@1+ (0.2,-25) [-25|26] "A"  MBMU,PC

BO_ 2332950394 D2M_SUMDATA2__58: 8 DCDC
 SG_ D2M_SUMDATA2_CRC_58 : 0|8@1+ (1,0) [0|255] ""  MBMU,PC
 SG_ D2M_DCDC_Output_Voltage_58 : 8|16@1+ (0.01,-200) [-200|455.35] "V"  MBMU,PC
 SG_ D2M_DCDC_Input_Voltage_58 : 24|16@1+ (0.05,0) [0|3276.75] "V"  MBMU,PC
 SG_ D2M_DCDC_Output_Current_58 : 40|16@1+ (0.05,-2000) [-2000|1276.75] "A"  MBMU,PC
 SG_ D2M_DCDC_Input_Current_58 : 56|8@1+ (0.2,-25) [-25|26] "A"  MBMU,PC

BO_ 2332950395 D2M_SUMDATA2__59: 8 DCDC
 SG_ D2M_SUMDATA2_CRC_59 : 0|8@1+ (1,0) [0|255] ""  MBMU,PC
 SG_ D2M_DCDC_Output_Voltage_59 : 8|16@1+ (0.01,-200) [-200|455.35] "V"  MBMU,PC
 SG_ D2M_DCDC_Input_Voltage_59 : 24|16@1+ (0.05,0) [0|3276.75] "V"  MBMU,PC
 SG_ D2M_DCDC_Output_Current_59 : 40|16@1+ (0.05,-2000) [-2000|1276.75] "A"  MBMU,PC
 SG_ D2M_DCDC_Input_Current_59 : 56|8@1+ (0.2,-25) [-25|26] "A"  MBMU,PC

BO_ 2332950396 D2M_SUMDATA2__60: 8 DCDC
 SG_ D2M_SUMDATA2_CRC_60 : 0|8@1+ (1,0) [0|255] ""  MBMU,PC
 SG_ D2M_DCDC_Output_Voltage_60 : 8|16@1+ (0.01,-200) [-200|455.35] "V"  MBMU,PC
 SG_ D2M_DCDC_Input_Voltage_60 : 24|16@1+ (0.05,0) [0|3276.75] "V"  MBMU,PC
 SG_ D2M_DCDC_Output_Current_60 : 40|16@1+ (0.05,-2000) [-2000|1276.75] "A"  MBMU,PC
 SG_ D2M_DCDC_Input_Current_60 : 56|8@1+ (0.2,-25) [-25|26] "A"  MBMU,PC

BO_ 2332950397 D2M_SUMDATA2__61: 8 DCDC
 SG_ D2M_SUMDATA2_CRC_61 : 0|8@1+ (1,0) [0|255] ""  MBMU,PC
 SG_ D2M_DCDC_Output_Voltage_61 : 8|16@1+ (0.01,-200) [-200|455.35] "V"  MBMU,PC
 SG_ D2M_DCDC_Input_Voltage_61 : 24|16@1+ (0.05,0) [0|3276.75] "V"  MBMU,PC
 SG_ D2M_DCDC_Output_Current_61 : 40|16@1+ (0.05,-2000) [-2000|1276.75] "A"  MBMU,PC
 SG_ D2M_DCDC_Input_Current_61 : 56|8@1+ (0.2,-25) [-25|26] "A"  MBMU,PC

BO_ 2332950398 D2M_SUMDATA2__62: 8 DCDC
 SG_ D2M_SUMDATA2_CRC_62 : 0|8@1+ (1,0) [0|255] ""  MBMU,PC
 SG_ D2M_DCDC_Output_Voltage_62 : 8|16@1+ (0.01,-200) [-200|455.35] "V"  MBMU,PC
 SG_ D2M_DCDC_Input_Voltage_62 : 24|16@1+ (0.05,0) [0|3276.75] "V"  MBMU,PC
 SG_ D2M_DCDC_Output_Current_62 : 40|16@1+ (0.05,-2000) [-2000|1276.75] "A"  MBMU,PC
 SG_ D2M_DCDC_Input_Current_62 : 56|8@1+ (0.2,-25) [-25|26] "A"  MBMU,PC

BO_ 2332950399 D2M_SUMDATA2__63: 8 DCDC
 SG_ D2M_SUMDATA2_CRC_63 : 0|8@1+ (1,0) [0|255] ""  MBMU,PC
 SG_ D2M_DCDC_Output_Voltage_63 : 8|16@1+ (0.01,-200) [-200|455.35] "V"  MBMU,PC
 SG_ D2M_DCDC_Input_Voltage_63 : 24|16@1+ (0.05,0) [0|3276.75] "V"  MBMU,PC
 SG_ D2M_DCDC_Output_Current_63 : 40|16@1+ (0.05,-2000) [-2000|1276.75] "A"  MBMU,PC
 SG_ D2M_DCDC_Input_Current_63 : 56|8@1+ (0.2,-25) [-25|26] "A"  MBMU,PC

BO_ 2333015873 D2M_SUMDATA3__01: 8 DCDC
 SG_ D2M_SUMDATA3_CRC_01 : 0|8@1+ (1,0) [0|255] ""  MBMU,PC
 SG_ D2M_DCDCLVPowerCurrent_01 : 8|8@1+ (0.1,0) [0|25.5] "A"  MBMU,PC
 SG_ D2M_DCDCLVPowerVoltage_01 : 16|8@1+ (0.2,0) [0|51] "V"  MBMU,PC
 SG_ D2M_DCDCDischrgCrrntLimt_01 : 24|16@1+ (0.01,0) [0|655.35] "A"  MBMU,PC
 SG_ D2M_DCDCChrgeCrrnt_Limt_01 : 40|16@1+ (0.01,-500) [-500|155.35] "A"  MBMU,PC
 SG_ D2M_SUMDATA3_Reserved_01 : 56|8@1+ (1,0) [0|255] ""  MBMU,PC

BO_ 2333015874 D2M_SUMDATA3__02: 8 DCDC
 SG_ D2M_SUMDATA3_CRC_02 : 0|8@1+ (1,0) [0|255] ""  MBMU,PC
 SG_ D2M_DCDCLVPowerCurrent_02 : 8|8@1+ (0.1,0) [0|25.5] "A"  MBMU,PC
 SG_ D2M_DCDCLVPowerVoltage_02 : 16|8@1+ (0.2,0) [0|51] "V"  MBMU,PC
 SG_ D2M_DCDCDischrgCrrntLimt_02 : 24|16@1+ (0.01,0) [0|655.35] "A"  MBMU,PC
 SG_ D2M_DCDCChrgeCrrnt_Limt_02 : 40|16@1+ (0.01,-500) [-500|155.35] "A"  MBMU,PC
 SG_ D2M_SUMDATA3_Reserved_02 : 56|8@1+ (1,0) [0|255] ""  MBMU,PC

BO_ 2333015875 D2M_SUMDATA3__03: 8 DCDC
 SG_ D2M_SUMDATA3_CRC_03 : 0|8@1+ (1,0) [0|255] ""  MBMU,PC
 SG_ D2M_DCDCLVPowerCurrent_03 : 8|8@1+ (0.1,0) [0|25.5] "A"  MBMU,PC
 SG_ D2M_DCDCLVPowerVoltage_03 : 16|8@1+ (0.2,0) [0|51] "V"  MBMU,PC
 SG_ D2M_DCDCDischrgCrrntLimt_03 : 24|16@1+ (0.01,0) [0|655.35] "A"  MBMU,PC
 SG_ D2M_DCDCChrgeCrrnt_Limt_03 : 40|16@1+ (0.01,-500) [-500|155.35] "A"  MBMU,PC
 SG_ D2M_SUMDATA3_Reserved_03 : 56|8@1+ (1,0) [0|255] ""  MBMU,PC

BO_ 2333015876 D2M_SUMDATA3__04: 8 DCDC
 SG_ D2M_SUMDATA3_CRC_04 : 0|8@1+ (1,0) [0|255] ""  MBMU,PC
 SG_ D2M_DCDCLVPowerCurrent_04 : 8|8@1+ (0.1,0) [0|25.5] "A"  MBMU,PC
 SG_ D2M_DCDCLVPowerVoltage_04 : 16|8@1+ (0.2,0) [0|51] "V"  MBMU,PC
 SG_ D2M_DCDCDischrgCrrntLimt_04 : 24|16@1+ (0.01,0) [0|655.35] "A"  MBMU,PC
 SG_ D2M_DCDCChrgeCrrnt_Limt_04 : 40|16@1+ (0.01,-500) [-500|155.35] "A"  MBMU,PC
 SG_ D2M_SUMDATA3_Reserved_04 : 56|8@1+ (1,0) [0|255] ""  MBMU,PC

BO_ 2333015877 D2M_SUMDATA3__05: 8 DCDC
 SG_ D2M_SUMDATA3_CRC_05 : 0|8@1+ (1,0) [0|255] ""  MBMU,PC
 SG_ D2M_DCDCLVPowerCurrent_05 : 8|8@1+ (0.1,0) [0|25.5] "A"  MBMU,PC
 SG_ D2M_DCDCLVPowerVoltage_05 : 16|8@1+ (0.2,0) [0|51] "V"  MBMU,PC
 SG_ D2M_DCDCDischrgCrrntLimt_05 : 24|16@1+ (0.01,0) [0|655.35] "A"  MBMU,PC
 SG_ D2M_DCDCChrgeCrrnt_Limt_05 : 40|16@1+ (0.01,-500) [-500|155.35] "A"  MBMU,PC
 SG_ D2M_SUMDATA3_Reserved_05 : 56|8@1+ (1,0) [0|255] ""  MBMU,PC

BO_ 2333015878 D2M_SUMDATA3__06: 8 DCDC
 SG_ D2M_SUMDATA3_CRC_06 : 0|8@1+ (1,0) [0|255] ""  MBMU,PC
 SG_ D2M_DCDCLVPowerCurrent_06 : 8|8@1+ (0.1,0) [0|25.5] "A"  MBMU,PC
 SG_ D2M_DCDCLVPowerVoltage_06 : 16|8@1+ (0.2,0) [0|51] "V"  MBMU,PC
 SG_ D2M_DCDCDischrgCrrntLimt_06 : 24|16@1+ (0.01,0) [0|655.35] "A"  MBMU,PC
 SG_ D2M_DCDCChrgeCrrnt_Limt_06 : 40|16@1+ (0.01,-500) [-500|155.35] "A"  MBMU,PC
 SG_ D2M_SUMDATA3_Reserved_06 : 56|8@1+ (1,0) [0|255] ""  MBMU,PC

BO_ 2333015879 D2M_SUMDATA3__07: 8 DCDC
 SG_ D2M_SUMDATA3_CRC_07 : 0|8@1+ (1,0) [0|255] ""  MBMU,PC
 SG_ D2M_DCDCLVPowerCurrent_07 : 8|8@1+ (0.1,0) [0|25.5] "A"  MBMU,PC
 SG_ D2M_DCDCLVPowerVoltage_07 : 16|8@1+ (0.2,0) [0|51] "V"  MBMU,PC
 SG_ D2M_DCDCDischrgCrrntLimt_07 : 24|16@1+ (0.01,0) [0|655.35] "A"  MBMU,PC
 SG_ D2M_DCDCChrgeCrrnt_Limt_07 : 40|16@1+ (0.01,-500) [-500|155.35] "A"  MBMU,PC
 SG_ D2M_SUMDATA3_Reserved_07 : 56|8@1+ (1,0) [0|255] ""  MBMU,PC

BO_ 2333015880 D2M_SUMDATA3__08: 8 DCDC
 SG_ D2M_SUMDATA3_CRC_08 : 0|8@1+ (1,0) [0|255] ""  MBMU,PC
 SG_ D2M_DCDCLVPowerCurrent_08 : 8|8@1+ (0.1,0) [0|25.5] "A"  MBMU,PC
 SG_ D2M_DCDCLVPowerVoltage_08 : 16|8@1+ (0.2,0) [0|51] "V"  MBMU,PC
 SG_ D2M_DCDCDischrgCrrntLimt_08 : 24|16@1+ (0.01,0) [0|655.35] "A"  MBMU,PC
 SG_ D2M_DCDCChrgeCrrnt_Limt_08 : 40|16@1+ (0.01,-500) [-500|155.35] "A"  MBMU,PC
 SG_ D2M_SUMDATA3_Reserved_08 : 56|8@1+ (1,0) [0|255] ""  MBMU,PC

BO_ 2333015881 D2M_SUMDATA3__09: 8 DCDC
 SG_ D2M_SUMDATA3_CRC_09 : 0|8@1+ (1,0) [0|255] ""  MBMU,PC
 SG_ D2M_DCDCLVPowerCurrent_09 : 8|8@1+ (0.1,0) [0|25.5] "A"  MBMU,PC
 SG_ D2M_DCDCLVPowerVoltage_09 : 16|8@1+ (0.2,0) [0|51] "V"  MBMU,PC
 SG_ D2M_DCDCDischrgCrrntLimt_09 : 24|16@1+ (0.01,0) [0|655.35] "A"  MBMU,PC
 SG_ D2M_DCDCChrgeCrrnt_Limt_09 : 40|16@1+ (0.01,-500) [-500|155.35] "A"  MBMU,PC
 SG_ D2M_SUMDATA3_Reserved_09 : 56|8@1+ (1,0) [0|255] ""  MBMU,PC

BO_ 2333015882 D2M_SUMDATA3__10: 8 DCDC
 SG_ D2M_SUMDATA3_CRC_10 : 0|8@1+ (1,0) [0|255] ""  MBMU,PC
 SG_ D2M_DCDCLVPowerCurrent_10 : 8|8@1+ (0.1,0) [0|25.5] "A"  MBMU,PC
 SG_ D2M_DCDCLVPowerVoltage_10 : 16|8@1+ (0.2,0) [0|51] "V"  MBMU,PC
 SG_ D2M_DCDCDischrgCrrntLimt_10 : 24|16@1+ (0.01,0) [0|655.35] "A"  MBMU,PC
 SG_ D2M_DCDCChrgeCrrnt_Limt_10 : 40|16@1+ (0.01,-500) [-500|155.35] "A"  MBMU,PC
 SG_ D2M_SUMDATA3_Reserved_10 : 56|8@1+ (1,0) [0|255] ""  MBMU,PC

BO_ 2333015883 D2M_SUMDATA3__11: 8 DCDC
 SG_ D2M_SUMDATA3_CRC_11 : 0|8@1+ (1,0) [0|255] ""  MBMU,PC
 SG_ D2M_DCDCLVPowerCurrent_11 : 8|8@1+ (0.1,0) [0|25.5] "A"  MBMU,PC
 SG_ D2M_DCDCLVPowerVoltage_11 : 16|8@1+ (0.2,0) [0|51] "V"  MBMU,PC
 SG_ D2M_DCDCDischrgCrrntLimt_11 : 24|16@1+ (0.01,0) [0|655.35] "A"  MBMU,PC
 SG_ D2M_DCDCChrgeCrrnt_Limt_11 : 40|16@1+ (0.01,-500) [-500|155.35] "A"  MBMU,PC
 SG_ D2M_SUMDATA3_Reserved_11 : 56|8@1+ (1,0) [0|255] ""  MBMU,PC

BO_ 2333015884 D2M_SUMDATA3__12: 8 DCDC
 SG_ D2M_SUMDATA3_CRC_12 : 0|8@1+ (1,0) [0|255] ""  MBMU,PC
 SG_ D2M_DCDCLVPowerCurrent_12 : 8|8@1+ (0.1,0) [0|25.5] "A"  MBMU,PC
 SG_ D2M_DCDCLVPowerVoltage_12 : 16|8@1+ (0.2,0) [0|51] "V"  MBMU,PC
 SG_ D2M_DCDCDischrgCrrntLimt_12 : 24|16@1+ (0.01,0) [0|655.35] "A"  MBMU,PC
 SG_ D2M_DCDCChrgeCrrnt_Limt_12 : 40|16@1+ (0.01,-500) [-500|155.35] "A"  MBMU,PC
 SG_ D2M_SUMDATA3_Reserved_12 : 56|8@1+ (1,0) [0|255] ""  MBMU,PC

BO_ 2333015885 D2M_SUMDATA3__13: 8 DCDC
 SG_ D2M_SUMDATA3_CRC_13 : 0|8@1+ (1,0) [0|255] ""  MBMU,PC
 SG_ D2M_DCDCLVPowerCurrent_13 : 8|8@1+ (0.1,0) [0|25.5] "A"  MBMU,PC
 SG_ D2M_DCDCLVPowerVoltage_13 : 16|8@1+ (0.2,0) [0|51] "V"  MBMU,PC
 SG_ D2M_DCDCDischrgCrrntLimt_13 : 24|16@1+ (0.01,0) [0|655.35] "A"  MBMU,PC
 SG_ D2M_DCDCChrgeCrrnt_Limt_13 : 40|16@1+ (0.01,-500) [-500|155.35] "A"  MBMU,PC
 SG_ D2M_SUMDATA3_Reserved_13 : 56|8@1+ (1,0) [0|255] ""  MBMU,PC

BO_ 2333015886 D2M_SUMDATA3__14: 8 DCDC
 SG_ D2M_SUMDATA3_CRC_14 : 0|8@1+ (1,0) [0|255] ""  MBMU,PC
 SG_ D2M_DCDCLVPowerCurrent_14 : 8|8@1+ (0.1,0) [0|25.5] "A"  MBMU,PC
 SG_ D2M_DCDCLVPowerVoltage_14 : 16|8@1+ (0.2,0) [0|51] "V"  MBMU,PC
 SG_ D2M_DCDCDischrgCrrntLimt_14 : 24|16@1+ (0.01,0) [0|655.35] "A"  MBMU,PC
 SG_ D2M_DCDCChrgeCrrnt_Limt_14 : 40|16@1+ (0.01,-500) [-500|155.35] "A"  MBMU,PC
 SG_ D2M_SUMDATA3_Reserved_14 : 56|8@1+ (1,0) [0|255] ""  MBMU,PC

BO_ 2333015887 D2M_SUMDATA3__15: 8 DCDC
 SG_ D2M_SUMDATA3_CRC_15 : 0|8@1+ (1,0) [0|255] ""  MBMU,PC
 SG_ D2M_DCDCLVPowerCurrent_15 : 8|8@1+ (0.1,0) [0|25.5] "A"  MBMU,PC
 SG_ D2M_DCDCLVPowerVoltage_15 : 16|8@1+ (0.2,0) [0|51] "V"  MBMU,PC
 SG_ D2M_DCDCDischrgCrrntLimt_15 : 24|16@1+ (0.01,0) [0|655.35] "A"  MBMU,PC
 SG_ D2M_DCDCChrgeCrrnt_Limt_15 : 40|16@1+ (0.01,-500) [-500|155.35] "A"  MBMU,PC
 SG_ D2M_SUMDATA3_Reserved_15 : 56|8@1+ (1,0) [0|255] ""  MBMU,PC

BO_ 2333015888 D2M_SUMDATA3__16: 8 DCDC
 SG_ D2M_SUMDATA3_CRC_16 : 0|8@1+ (1,0) [0|255] ""  MBMU,PC
 SG_ D2M_DCDCLVPowerCurrent_16 : 8|8@1+ (0.1,0) [0|25.5] "A"  MBMU,PC
 SG_ D2M_DCDCLVPowerVoltage_16 : 16|8@1+ (0.2,0) [0|51] "V"  MBMU,PC
 SG_ D2M_DCDCDischrgCrrntLimt_16 : 24|16@1+ (0.01,0) [0|655.35] "A"  MBMU,PC
 SG_ D2M_DCDCChrgeCrrnt_Limt_16 : 40|16@1+ (0.01,-500) [-500|155.35] "A"  MBMU,PC
 SG_ D2M_SUMDATA3_Reserved_16 : 56|8@1+ (1,0) [0|255] ""  MBMU,PC

BO_ 2333015889 D2M_SUMDATA3__17: 8 DCDC
 SG_ D2M_SUMDATA3_CRC_17 : 0|8@1+ (1,0) [0|255] ""  MBMU,PC
 SG_ D2M_DCDCLVPowerCurrent_17 : 8|8@1+ (0.1,0) [0|25.5] "A"  MBMU,PC
 SG_ D2M_DCDCLVPowerVoltage_17 : 16|8@1+ (0.2,0) [0|51] "V"  MBMU,PC
 SG_ D2M_DCDCDischrgCrrntLimt_17 : 24|16@1+ (0.01,0) [0|655.35] "A"  MBMU,PC
 SG_ D2M_DCDCChrgeCrrnt_Limt_17 : 40|16@1+ (0.01,-500) [-500|155.35] "A"  MBMU,PC
 SG_ D2M_SUMDATA3_Reserved_17 : 56|8@1+ (1,0) [0|255] ""  MBMU,PC

BO_ 2333015890 D2M_SUMDATA3__18: 8 DCDC
 SG_ D2M_SUMDATA3_CRC_18 : 0|8@1+ (1,0) [0|255] ""  MBMU,PC
 SG_ D2M_DCDCLVPowerCurrent_18 : 8|8@1+ (0.1,0) [0|25.5] "A"  MBMU,PC
 SG_ D2M_DCDCLVPowerVoltage_18 : 16|8@1+ (0.2,0) [0|51] "V"  MBMU,PC
 SG_ D2M_DCDCDischrgCrrntLimt_18 : 24|16@1+ (0.01,0) [0|655.35] "A"  MBMU,PC
 SG_ D2M_DCDCChrgeCrrnt_Limt_18 : 40|16@1+ (0.01,-500) [-500|155.35] "A"  MBMU,PC
 SG_ D2M_SUMDATA3_Reserved_18 : 56|8@1+ (1,0) [0|255] ""  MBMU,PC

BO_ 2333015891 D2M_SUMDATA3__19: 8 DCDC
 SG_ D2M_SUMDATA3_CRC_19 : 0|8@1+ (1,0) [0|255] ""  MBMU,PC
 SG_ D2M_DCDCLVPowerCurrent_19 : 8|8@1+ (0.1,0) [0|25.5] "A"  MBMU,PC
 SG_ D2M_DCDCLVPowerVoltage_19 : 16|8@1+ (0.2,0) [0|51] "V"  MBMU,PC
 SG_ D2M_DCDCDischrgCrrntLimt_19 : 24|16@1+ (0.01,0) [0|655.35] "A"  MBMU,PC
 SG_ D2M_DCDCChrgeCrrnt_Limt_19 : 40|16@1+ (0.01,-500) [-500|155.35] "A"  MBMU,PC
 SG_ D2M_SUMDATA3_Reserved_19 : 56|8@1+ (1,0) [0|255] ""  MBMU,PC

BO_ 2333015892 D2M_SUMDATA3__20: 8 DCDC
 SG_ D2M_SUMDATA3_CRC_20 : 0|8@1+ (1,0) [0|255] ""  MBMU,PC
 SG_ D2M_DCDCLVPowerCurrent_20 : 8|8@1+ (0.1,0) [0|25.5] "A"  MBMU,PC
 SG_ D2M_DCDCLVPowerVoltage_20 : 16|8@1+ (0.2,0) [0|51] "V"  MBMU,PC
 SG_ D2M_DCDCDischrgCrrntLimt_20 : 24|16@1+ (0.01,0) [0|655.35] "A"  MBMU,PC
 SG_ D2M_DCDCChrgeCrrnt_Limt_20 : 40|16@1+ (0.01,-500) [-500|155.35] "A"  MBMU,PC
 SG_ D2M_SUMDATA3_Reserved_20 : 56|8@1+ (1,0) [0|255] ""  MBMU,PC

BO_ 2333015893 D2M_SUMDATA3__21: 8 DCDC
 SG_ D2M_SUMDATA3_CRC_21 : 0|8@1+ (1,0) [0|255] ""  MBMU,PC
 SG_ D2M_DCDCLVPowerCurrent_21 : 8|8@1+ (0.1,0) [0|25.5] "A"  MBMU,PC
 SG_ D2M_DCDCLVPowerVoltage_21 : 16|8@1+ (0.2,0) [0|51] "V"  MBMU,PC
 SG_ D2M_DCDCDischrgCrrntLimt_21 : 24|16@1+ (0.01,0) [0|655.35] "A"  MBMU,PC
 SG_ D2M_DCDCChrgeCrrnt_Limt_21 : 40|16@1+ (0.01,-500) [-500|155.35] "A"  MBMU,PC
 SG_ D2M_SUMDATA3_Reserved_21 : 56|8@1+ (1,0) [0|255] ""  MBMU,PC

BO_ 2333015894 D2M_SUMDATA3__22: 8 DCDC
 SG_ D2M_SUMDATA3_CRC_22 : 0|8@1+ (1,0) [0|255] ""  MBMU,PC
 SG_ D2M_DCDCLVPowerCurrent_22 : 8|8@1+ (0.1,0) [0|25.5] "A"  MBMU,PC
 SG_ D2M_DCDCLVPowerVoltage_22 : 16|8@1+ (0.2,0) [0|51] "V"  MBMU,PC
 SG_ D2M_DCDCDischrgCrrntLimt_22 : 24|16@1+ (0.01,0) [0|655.35] "A"  MBMU,PC
 SG_ D2M_DCDCChrgeCrrnt_Limt_22 : 40|16@1+ (0.01,-500) [-500|155.35] "A"  MBMU,PC
 SG_ D2M_SUMDATA3_Reserved_22 : 56|8@1+ (1,0) [0|255] ""  MBMU,PC

BO_ 2333015895 D2M_SUMDATA3__23: 8 DCDC
 SG_ D2M_SUMDATA3_CRC_23 : 0|8@1+ (1,0) [0|255] ""  MBMU,PC
 SG_ D2M_DCDCLVPowerCurrent_23 : 8|8@1+ (0.1,0) [0|25.5] "A"  MBMU,PC
 SG_ D2M_DCDCLVPowerVoltage_23 : 16|8@1+ (0.2,0) [0|51] "V"  MBMU,PC
 SG_ D2M_DCDCDischrgCrrntLimt_23 : 24|16@1+ (0.01,0) [0|655.35] "A"  MBMU,PC
 SG_ D2M_DCDCChrgeCrrnt_Limt_23 : 40|16@1+ (0.01,-500) [-500|155.35] "A"  MBMU,PC
 SG_ D2M_SUMDATA3_Reserved_23 : 56|8@1+ (1,0) [0|255] ""  MBMU,PC

BO_ 2333015896 D2M_SUMDATA3__24: 8 DCDC
 SG_ D2M_SUMDATA3_CRC_24 : 0|8@1+ (1,0) [0|255] ""  MBMU,PC
 SG_ D2M_DCDCLVPowerCurrent_24 : 8|8@1+ (0.1,0) [0|25.5] "A"  MBMU,PC
 SG_ D2M_DCDCLVPowerVoltage_24 : 16|8@1+ (0.2,0) [0|51] "V"  MBMU,PC
 SG_ D2M_DCDCDischrgCrrntLimt_24 : 24|16@1+ (0.01,0) [0|655.35] "A"  MBMU,PC
 SG_ D2M_DCDCChrgeCrrnt_Limt_24 : 40|16@1+ (0.01,-500) [-500|155.35] "A"  MBMU,PC
 SG_ D2M_SUMDATA3_Reserved_24 : 56|8@1+ (1,0) [0|255] ""  MBMU,PC

BO_ 2333015897 D2M_SUMDATA3__25: 8 DCDC
 SG_ D2M_SUMDATA3_CRC_25 : 0|8@1+ (1,0) [0|255] ""  MBMU,PC
 SG_ D2M_DCDCLVPowerCurrent_25 : 8|8@1+ (0.1,0) [0|25.5] "A"  MBMU,PC
 SG_ D2M_DCDCLVPowerVoltage_25 : 16|8@1+ (0.2,0) [0|51] "V"  MBMU,PC
 SG_ D2M_DCDCDischrgCrrntLimt_25 : 24|16@1+ (0.01,0) [0|655.35] "A"  MBMU,PC
 SG_ D2M_DCDCChrgeCrrnt_Limt_25 : 40|16@1+ (0.01,-500) [-500|155.35] "A"  MBMU,PC
 SG_ D2M_SUMDATA3_Reserved_25 : 56|8@1+ (1,0) [0|255] ""  MBMU,PC

BO_ 2333015898 D2M_SUMDATA3__26: 8 DCDC
 SG_ D2M_SUMDATA3_CRC_26 : 0|8@1+ (1,0) [0|255] ""  MBMU,PC
 SG_ D2M_DCDCLVPowerCurrent_26 : 8|8@1+ (0.1,0) [0|25.5] "A"  MBMU,PC
 SG_ D2M_DCDCLVPowerVoltage_26 : 16|8@1+ (0.2,0) [0|51] "V"  MBMU,PC
 SG_ D2M_DCDCDischrgCrrntLimt_26 : 24|16@1+ (0.01,0) [0|655.35] "A"  MBMU,PC
 SG_ D2M_DCDCChrgeCrrnt_Limt_26 : 40|16@1+ (0.01,-500) [-500|155.35] "A"  MBMU,PC
 SG_ D2M_SUMDATA3_Reserved_26 : 56|8@1+ (1,0) [0|255] ""  MBMU,PC

BO_ 2333015899 D2M_SUMDATA3__27: 8 DCDC
 SG_ D2M_SUMDATA3_CRC_27 : 0|8@1+ (1,0) [0|255] ""  MBMU,PC
 SG_ D2M_DCDCLVPowerCurrent_27 : 8|8@1+ (0.1,0) [0|25.5] "A"  MBMU,PC
 SG_ D2M_DCDCLVPowerVoltage_27 : 16|8@1+ (0.2,0) [0|51] "V"  MBMU,PC
 SG_ D2M_DCDCDischrgCrrntLimt_27 : 24|16@1+ (0.01,0) [0|655.35] "A"  MBMU,PC
 SG_ D2M_DCDCChrgeCrrnt_Limt_27 : 40|16@1+ (0.01,-500) [-500|155.35] "A"  MBMU,PC
 SG_ D2M_SUMDATA3_Reserved_27 : 56|8@1+ (1,0) [0|255] ""  MBMU,PC

BO_ 2333015900 D2M_SUMDATA3__28: 8 DCDC
 SG_ D2M_SUMDATA3_CRC_28 : 0|8@1+ (1,0) [0|255] ""  MBMU,PC
 SG_ D2M_DCDCLVPowerCurrent_28 : 8|8@1+ (0.1,0) [0|25.5] "A"  MBMU,PC
 SG_ D2M_DCDCLVPowerVoltage_28 : 16|8@1+ (0.2,0) [0|51] "V"  MBMU,PC
 SG_ D2M_DCDCDischrgCrrntLimt_28 : 24|16@1+ (0.01,0) [0|655.35] "A"  MBMU,PC
 SG_ D2M_DCDCChrgeCrrnt_Limt_28 : 40|16@1+ (0.01,-500) [-500|155.35] "A"  MBMU,PC
 SG_ D2M_SUMDATA3_Reserved_28 : 56|8@1+ (1,0) [0|255] ""  MBMU,PC

BO_ 2333015901 D2M_SUMDATA3__29: 8 DCDC
 SG_ D2M_SUMDATA3_CRC_29 : 0|8@1+ (1,0) [0|255] ""  MBMU,PC
 SG_ D2M_DCDCLVPowerCurrent_29 : 8|8@1+ (0.1,0) [0|25.5] "A"  MBMU,PC
 SG_ D2M_DCDCLVPowerVoltage_29 : 16|8@1+ (0.2,0) [0|51] "V"  MBMU,PC
 SG_ D2M_DCDCDischrgCrrntLimt_29 : 24|16@1+ (0.01,0) [0|655.35] "A"  MBMU,PC
 SG_ D2M_DCDCChrgeCrrnt_Limt_29 : 40|16@1+ (0.01,-500) [-500|155.35] "A"  MBMU,PC
 SG_ D2M_SUMDATA3_Reserved_29 : 56|8@1+ (1,0) [0|255] ""  MBMU,PC

BO_ 2333015902 D2M_SUMDATA3__30: 8 DCDC
 SG_ D2M_SUMDATA3_CRC_30 : 0|8@1+ (1,0) [0|255] ""  MBMU,PC
 SG_ D2M_DCDCLVPowerCurrent_30 : 8|8@1+ (0.1,0) [0|25.5] "A"  MBMU,PC
 SG_ D2M_DCDCLVPowerVoltage_30 : 16|8@1+ (0.2,0) [0|51] "V"  MBMU,PC
 SG_ D2M_DCDCDischrgCrrntLimt_30 : 24|16@1+ (0.01,0) [0|655.35] "A"  MBMU,PC
 SG_ D2M_DCDCChrgeCrrnt_Limt_30 : 40|16@1+ (0.01,-500) [-500|155.35] "A"  MBMU,PC
 SG_ D2M_SUMDATA3_Reserved_30 : 56|8@1+ (1,0) [0|255] ""  MBMU,PC

BO_ 2333015903 D2M_SUMDATA3__31: 8 DCDC
 SG_ D2M_SUMDATA3_CRC_31 : 0|8@1+ (1,0) [0|255] ""  MBMU,PC
 SG_ D2M_DCDCLVPowerCurrent_31 : 8|8@1+ (0.1,0) [0|25.5] "A"  MBMU,PC
 SG_ D2M_DCDCLVPowerVoltage_31 : 16|8@1+ (0.2,0) [0|51] "V"  MBMU,PC
 SG_ D2M_DCDCDischrgCrrntLimt_31 : 24|16@1+ (0.01,0) [0|655.35] "A"  MBMU,PC
 SG_ D2M_DCDCChrgeCrrnt_Limt_31 : 40|16@1+ (0.01,-500) [-500|155.35] "A"  MBMU,PC
 SG_ D2M_SUMDATA3_Reserved_31 : 56|8@1+ (1,0) [0|255] ""  MBMU,PC

BO_ 2333015904 D2M_SUMDATA3__32: 8 DCDC
 SG_ D2M_SUMDATA3_CRC_32 : 0|8@1+ (1,0) [0|255] ""  MBMU,PC
 SG_ D2M_DCDCLVPowerCurrent_32 : 8|8@1+ (0.1,0) [0|25.5] "A"  MBMU,PC
 SG_ D2M_DCDCLVPowerVoltage_32 : 16|8@1+ (0.2,0) [0|51] "V"  MBMU,PC
 SG_ D2M_DCDCDischrgCrrntLimt_32 : 24|16@1+ (0.01,0) [0|655.35] "A"  MBMU,PC
 SG_ D2M_DCDCChrgeCrrnt_Limt_32 : 40|16@1+ (0.01,-500) [-500|155.35] "A"  MBMU,PC
 SG_ D2M_SUMDATA3_Reserved_32 : 56|8@1+ (1,0) [0|255] ""  MBMU,PC

BO_ 2333015905 D2M_SUMDATA3__33: 8 DCDC
 SG_ D2M_SUMDATA3_CRC_33 : 0|8@1+ (1,0) [0|255] ""  MBMU,PC
 SG_ D2M_DCDCLVPowerCurrent_33 : 8|8@1+ (0.1,0) [0|25.5] "A"  MBMU,PC
 SG_ D2M_DCDCLVPowerVoltage_33 : 16|8@1+ (0.2,0) [0|51] "V"  MBMU,PC
 SG_ D2M_DCDCDischrgCrrntLimt_33 : 24|16@1+ (0.01,0) [0|655.35] "A"  MBMU,PC
 SG_ D2M_DCDCChrgeCrrnt_Limt_33 : 40|16@1+ (0.01,-500) [-500|155.35] "A"  MBMU,PC
 SG_ D2M_SUMDATA3_Reserved_33 : 56|8@1+ (1,0) [0|255] ""  MBMU,PC

BO_ 2333015906 D2M_SUMDATA3__34: 8 DCDC
 SG_ D2M_SUMDATA3_CRC_34 : 0|8@1+ (1,0) [0|255] ""  MBMU,PC
 SG_ D2M_DCDCLVPowerCurrent_34 : 8|8@1+ (0.1,0) [0|25.5] "A"  MBMU,PC
 SG_ D2M_DCDCLVPowerVoltage_34 : 16|8@1+ (0.2,0) [0|51] "V"  MBMU,PC
 SG_ D2M_DCDCDischrgCrrntLimt_34 : 24|16@1+ (0.01,0) [0|655.35] "A"  MBMU,PC
 SG_ D2M_DCDCChrgeCrrnt_Limt_34 : 40|16@1+ (0.01,-500) [-500|155.35] "A"  MBMU,PC
 SG_ D2M_SUMDATA3_Reserved_34 : 56|8@1+ (1,0) [0|255] ""  MBMU,PC

BO_ 2333015907 D2M_SUMDATA3__35: 8 DCDC
 SG_ D2M_SUMDATA3_CRC_35 : 0|8@1+ (1,0) [0|255] ""  MBMU,PC
 SG_ D2M_DCDCLVPowerCurrent_35 : 8|8@1+ (0.1,0) [0|25.5] "A"  MBMU,PC
 SG_ D2M_DCDCLVPowerVoltage_35 : 16|8@1+ (0.2,0) [0|51] "V"  MBMU,PC
 SG_ D2M_DCDCDischrgCrrntLimt_35 : 24|16@1+ (0.01,0) [0|655.35] "A"  MBMU,PC
 SG_ D2M_DCDCChrgeCrrnt_Limt_35 : 40|16@1+ (0.01,-500) [-500|155.35] "A"  MBMU,PC
 SG_ D2M_SUMDATA3_Reserved_35 : 56|8@1+ (1,0) [0|255] ""  MBMU,PC

BO_ 2333015908 D2M_SUMDATA3__36: 8 DCDC
 SG_ D2M_SUMDATA3_CRC_36 : 0|8@1+ (1,0) [0|255] ""  MBMU,PC
 SG_ D2M_DCDCLVPowerCurrent_36 : 8|8@1+ (0.1,0) [0|25.5] "A"  MBMU,PC
 SG_ D2M_DCDCLVPowerVoltage_36 : 16|8@1+ (0.2,0) [0|51] "V"  MBMU,PC
 SG_ D2M_DCDCDischrgCrrntLimt_36 : 24|16@1+ (0.01,0) [0|655.35] "A"  MBMU,PC
 SG_ D2M_DCDCChrgeCrrnt_Limt_36 : 40|16@1+ (0.01,-500) [-500|155.35] "A"  MBMU,PC
 SG_ D2M_SUMDATA3_Reserved_36 : 56|8@1+ (1,0) [0|255] ""  MBMU,PC

BO_ 2333015909 D2M_SUMDATA3__37: 8 DCDC
 SG_ D2M_SUMDATA3_CRC_37 : 0|8@1+ (1,0) [0|255] ""  MBMU,PC
 SG_ D2M_DCDCLVPowerCurrent_37 : 8|8@1+ (0.1,0) [0|25.5] "A"  MBMU,PC
 SG_ D2M_DCDCLVPowerVoltage_37 : 16|8@1+ (0.2,0) [0|51] "V"  MBMU,PC
 SG_ D2M_DCDCDischrgCrrntLimt_37 : 24|16@1+ (0.01,0) [0|655.35] "A"  MBMU,PC
 SG_ D2M_DCDCChrgeCrrnt_Limt_37 : 40|16@1+ (0.01,-500) [-500|155.35] "A"  MBMU,PC
 SG_ D2M_SUMDATA3_Reserved_37 : 56|8@1+ (1,0) [0|255] ""  MBMU,PC

BO_ 2333015910 D2M_SUMDATA3__38: 8 DCDC
 SG_ D2M_SUMDATA3_CRC_38 : 0|8@1+ (1,0) [0|255] ""  MBMU,PC
 SG_ D2M_DCDCLVPowerCurrent_38 : 8|8@1+ (0.1,0) [0|25.5] "A"  MBMU,PC
 SG_ D2M_DCDCLVPowerVoltage_38 : 16|8@1+ (0.2,0) [0|51] "V"  MBMU,PC
 SG_ D2M_DCDCDischrgCrrntLimt_38 : 24|16@1+ (0.01,0) [0|655.35] "A"  MBMU,PC
 SG_ D2M_DCDCChrgeCrrnt_Limt_38 : 40|16@1+ (0.01,-500) [-500|155.35] "A"  MBMU,PC
 SG_ D2M_SUMDATA3_Reserved_38 : 56|8@1+ (1,0) [0|255] ""  MBMU,PC

BO_ 2333015911 D2M_SUMDATA3__39: 8 DCDC
 SG_ D2M_SUMDATA3_CRC_39 : 0|8@1+ (1,0) [0|255] ""  MBMU,PC
 SG_ D2M_DCDCLVPowerCurrent_39 : 8|8@1+ (0.1,0) [0|25.5] "A"  MBMU,PC
 SG_ D2M_DCDCLVPowerVoltage_39 : 16|8@1+ (0.2,0) [0|51] "V"  MBMU,PC
 SG_ D2M_DCDCDischrgCrrntLimt_39 : 24|16@1+ (0.01,0) [0|655.35] "A"  MBMU,PC
 SG_ D2M_DCDCChrgeCrrnt_Limt_39 : 40|16@1+ (0.01,-500) [-500|155.35] "A"  MBMU,PC
 SG_ D2M_SUMDATA3_Reserved_39 : 56|8@1+ (1,0) [0|255] ""  MBMU,PC

BO_ 2333015912 D2M_SUMDATA3__40: 8 DCDC
 SG_ D2M_SUMDATA3_CRC_40 : 0|8@1+ (1,0) [0|255] ""  MBMU,PC
 SG_ D2M_DCDCLVPowerCurrent_40 : 8|8@1+ (0.1,0) [0|25.5] "A"  MBMU,PC
 SG_ D2M_DCDCLVPowerVoltage_40 : 16|8@1+ (0.2,0) [0|51] "V"  MBMU,PC
 SG_ D2M_DCDCDischrgCrrntLimt_40 : 24|16@1+ (0.01,0) [0|655.35] "A"  MBMU,PC
 SG_ D2M_DCDCChrgeCrrnt_Limt_40 : 40|16@1+ (0.01,-500) [-500|155.35] "A"  MBMU,PC
 SG_ D2M_SUMDATA3_Reserved_40 : 56|8@1+ (1,0) [0|255] ""  MBMU,PC

BO_ 2333015913 D2M_SUMDATA3__41: 8 DCDC
 SG_ D2M_SUMDATA3_CRC_41 : 0|8@1+ (1,0) [0|255] ""  MBMU,PC
 SG_ D2M_DCDCLVPowerCurrent_41 : 8|8@1+ (0.1,0) [0|25.5] "A"  MBMU,PC
 SG_ D2M_DCDCLVPowerVoltage_41 : 16|8@1+ (0.2,0) [0|51] "V"  MBMU,PC
 SG_ D2M_DCDCDischrgCrrntLimt_41 : 24|16@1+ (0.01,0) [0|655.35] "A"  MBMU,PC
 SG_ D2M_DCDCChrgeCrrnt_Limt_41 : 40|16@1+ (0.01,-500) [-500|155.35] "A"  MBMU,PC
 SG_ D2M_SUMDATA3_Reserved_41 : 56|8@1+ (1,0) [0|255] ""  MBMU,PC

BO_ 2333015914 D2M_SUMDATA3__42: 8 DCDC
 SG_ D2M_SUMDATA3_CRC_42 : 0|8@1+ (1,0) [0|255] ""  MBMU,PC
 SG_ D2M_DCDCLVPowerCurrent_42 : 8|8@1+ (0.1,0) [0|25.5] "A"  MBMU,PC
 SG_ D2M_DCDCLVPowerVoltage_42 : 16|8@1+ (0.2,0) [0|51] "V"  MBMU,PC
 SG_ D2M_DCDCDischrgCrrntLimt_42 : 24|16@1+ (0.01,0) [0|655.35] "A"  MBMU,PC
 SG_ D2M_DCDCChrgeCrrnt_Limt_42 : 40|16@1+ (0.01,-500) [-500|155.35] "A"  MBMU,PC
 SG_ D2M_SUMDATA3_Reserved_42 : 56|8@1+ (1,0) [0|255] ""  MBMU,PC

BO_ 2333015915 D2M_SUMDATA3__43: 8 DCDC
 SG_ D2M_SUMDATA3_CRC_43 : 0|8@1+ (1,0) [0|255] ""  MBMU,PC
 SG_ D2M_DCDCLVPowerCurrent_43 : 8|8@1+ (0.1,0) [0|25.5] "A"  MBMU,PC
 SG_ D2M_DCDCLVPowerVoltage_43 : 16|8@1+ (0.2,0) [0|51] "V"  MBMU,PC
 SG_ D2M_DCDCDischrgCrrntLimt_43 : 24|16@1+ (0.01,0) [0|655.35] "A"  MBMU,PC
 SG_ D2M_DCDCChrgeCrrnt_Limt_43 : 40|16@1+ (0.01,-500) [-500|155.35] "A"  MBMU,PC
 SG_ D2M_SUMDATA3_Reserved_43 : 56|8@1+ (1,0) [0|255] ""  MBMU,PC

BO_ 2333015916 D2M_SUMDATA3__44: 8 DCDC
 SG_ D2M_SUMDATA3_CRC_44 : 0|8@1+ (1,0) [0|255] ""  MBMU,PC
 SG_ D2M_DCDCLVPowerCurrent_44 : 8|8@1+ (0.1,0) [0|25.5] "A"  MBMU,PC
 SG_ D2M_DCDCLVPowerVoltage_44 : 16|8@1+ (0.2,0) [0|51] "V"  MBMU,PC
 SG_ D2M_DCDCDischrgCrrntLimt_44 : 24|16@1+ (0.01,0) [0|655.35] "A"  MBMU,PC
 SG_ D2M_DCDCChrgeCrrnt_Limt_44 : 40|16@1+ (0.01,-500) [-500|155.35] "A"  MBMU,PC
 SG_ D2M_SUMDATA3_Reserved_44 : 56|8@1+ (1,0) [0|255] ""  MBMU,PC

BO_ 2333015917 D2M_SUMDATA3__45: 8 DCDC
 SG_ D2M_SUMDATA3_CRC_45 : 0|8@1+ (1,0) [0|255] ""  MBMU,PC
 SG_ D2M_DCDCLVPowerCurrent_45 : 8|8@1+ (0.1,0) [0|25.5] "A"  MBMU,PC
 SG_ D2M_DCDCLVPowerVoltage_45 : 16|8@1+ (0.2,0) [0|51] "V"  MBMU,PC
 SG_ D2M_DCDCDischrgCrrntLimt_45 : 24|16@1+ (0.01,0) [0|655.35] "A"  MBMU,PC
 SG_ D2M_DCDCChrgeCrrnt_Limt_45 : 40|16@1+ (0.01,-500) [-500|155.35] "A"  MBMU,PC
 SG_ D2M_SUMDATA3_Reserved_45 : 56|8@1+ (1,0) [0|255] ""  MBMU,PC

BO_ 2333015918 D2M_SUMDATA3__46: 8 DCDC
 SG_ D2M_SUMDATA3_CRC_46 : 0|8@1+ (1,0) [0|255] ""  MBMU,PC
 SG_ D2M_DCDCLVPowerCurrent_46 : 8|8@1+ (0.1,0) [0|25.5] "A"  MBMU,PC
 SG_ D2M_DCDCLVPowerVoltage_46 : 16|8@1+ (0.2,0) [0|51] "V"  MBMU,PC
 SG_ D2M_DCDCDischrgCrrntLimt_46 : 24|16@1+ (0.01,0) [0|655.35] "A"  MBMU,PC
 SG_ D2M_DCDCChrgeCrrnt_Limt_46 : 40|16@1+ (0.01,-500) [-500|155.35] "A"  MBMU,PC
 SG_ D2M_SUMDATA3_Reserved_46 : 56|8@1+ (1,0) [0|255] ""  MBMU,PC

BO_ 2333015919 D2M_SUMDATA3__47: 8 DCDC
 SG_ D2M_SUMDATA3_CRC_47 : 0|8@1+ (1,0) [0|255] ""  MBMU,PC
 SG_ D2M_DCDCLVPowerCurrent_47 : 8|8@1+ (0.1,0) [0|25.5] "A"  MBMU,PC
 SG_ D2M_DCDCLVPowerVoltage_47 : 16|8@1+ (0.2,0) [0|51] "V"  MBMU,PC
 SG_ D2M_DCDCDischrgCrrntLimt_47 : 24|16@1+ (0.01,0) [0|655.35] "A"  MBMU,PC
 SG_ D2M_DCDCChrgeCrrnt_Limt_47 : 40|16@1+ (0.01,-500) [-500|155.35] "A"  MBMU,PC
 SG_ D2M_SUMDATA3_Reserved_47 : 56|8@1+ (1,0) [0|255] ""  MBMU,PC

BO_ 2333015920 D2M_SUMDATA3__48: 8 DCDC
 SG_ D2M_SUMDATA3_CRC_48 : 0|8@1+ (1,0) [0|255] ""  MBMU,PC
 SG_ D2M_DCDCLVPowerCurrent_48 : 8|8@1+ (0.1,0) [0|25.5] "A"  MBMU,PC
 SG_ D2M_DCDCLVPowerVoltage_48 : 16|8@1+ (0.2,0) [0|51] "V"  MBMU,PC
 SG_ D2M_DCDCDischrgCrrntLimt_48 : 24|16@1+ (0.01,0) [0|655.35] "A"  MBMU,PC
 SG_ D2M_DCDCChrgeCrrnt_Limt_48 : 40|16@1+ (0.01,-500) [-500|155.35] "A"  MBMU,PC
 SG_ D2M_SUMDATA3_Reserved_48 : 56|8@1+ (1,0) [0|255] ""  MBMU,PC

BO_ 2333015921 D2M_SUMDATA3__49: 8 DCDC
 SG_ D2M_SUMDATA3_CRC_49 : 0|8@1+ (1,0) [0|255] ""  MBMU,PC
 SG_ D2M_DCDCLVPowerCurrent_49 : 8|8@1+ (0.1,0) [0|25.5] "A"  MBMU,PC
 SG_ D2M_DCDCLVPowerVoltage_49 : 16|8@1+ (0.2,0) [0|51] "V"  MBMU,PC
 SG_ D2M_DCDCDischrgCrrntLimt_49 : 24|16@1+ (0.01,0) [0|655.35] "A"  MBMU,PC
 SG_ D2M_DCDCChrgeCrrnt_Limt_49 : 40|16@1+ (0.01,-500) [-500|155.35] "A"  MBMU,PC
 SG_ D2M_SUMDATA3_Reserved_49 : 56|8@1+ (1,0) [0|255] ""  MBMU,PC

BO_ 2333015922 D2M_SUMDATA3__50: 8 DCDC
 SG_ D2M_SUMDATA3_CRC_50 : 0|8@1+ (1,0) [0|255] ""  MBMU,PC
 SG_ D2M_DCDCLVPowerCurrent_50 : 8|8@1+ (0.1,0) [0|25.5] "A"  MBMU,PC
 SG_ D2M_DCDCLVPowerVoltage_50 : 16|8@1+ (0.2,0) [0|51] "V"  MBMU,PC
 SG_ D2M_DCDCDischrgCrrntLimt_50 : 24|16@1+ (0.01,0) [0|655.35] "A"  MBMU,PC
 SG_ D2M_DCDCChrgeCrrnt_Limt_50 : 40|16@1+ (0.01,-500) [-500|155.35] "A"  MBMU,PC
 SG_ D2M_SUMDATA3_Reserved_50 : 56|8@1+ (1,0) [0|255] ""  MBMU,PC

BO_ 2333015923 D2M_SUMDATA3__51: 8 DCDC
 SG_ D2M_SUMDATA3_CRC_51 : 0|8@1+ (1,0) [0|255] ""  MBMU,PC
 SG_ D2M_DCDCLVPowerCurrent_51 : 8|8@1+ (0.1,0) [0|25.5] "A"  MBMU,PC
 SG_ D2M_DCDCLVPowerVoltage_51 : 16|8@1+ (0.2,0) [0|51] "V"  MBMU,PC
 SG_ D2M_DCDCDischrgCrrntLimt_51 : 24|16@1+ (0.01,0) [0|655.35] "A"  MBMU,PC
 SG_ D2M_DCDCChrgeCrrnt_Limt_51 : 40|16@1+ (0.01,-500) [-500|155.35] "A"  MBMU,PC
 SG_ D2M_SUMDATA3_Reserved_51 : 56|8@1+ (1,0) [0|255] ""  MBMU,PC

BO_ 2333015924 D2M_SUMDATA3__52: 8 DCDC
 SG_ D2M_SUMDATA3_CRC_52 : 0|8@1+ (1,0) [0|255] ""  MBMU,PC
 SG_ D2M_DCDCLVPowerCurrent_52 : 8|8@1+ (0.1,0) [0|25.5] "A"  MBMU,PC
 SG_ D2M_DCDCLVPowerVoltage_52 : 16|8@1+ (0.2,0) [0|51] "V"  MBMU,PC
 SG_ D2M_DCDCDischrgCrrntLimt_52 : 24|16@1+ (0.01,0) [0|655.35] "A"  MBMU,PC
 SG_ D2M_DCDCChrgeCrrnt_Limt_52 : 40|16@1+ (0.01,-500) [-500|155.35] "A"  MBMU,PC
 SG_ D2M_SUMDATA3_Reserved_52 : 56|8@1+ (1,0) [0|255] ""  MBMU,PC

BO_ 2333015925 D2M_SUMDATA3__53: 8 DCDC
 SG_ D2M_SUMDATA3_CRC_53 : 0|8@1+ (1,0) [0|255] ""  MBMU,PC
 SG_ D2M_DCDCLVPowerCurrent_53 : 8|8@1+ (0.1,0) [0|25.5] "A"  MBMU,PC
 SG_ D2M_DCDCLVPowerVoltage_53 : 16|8@1+ (0.2,0) [0|51] "V"  MBMU,PC
 SG_ D2M_DCDCDischrgCrrntLimt_53 : 24|16@1+ (0.01,0) [0|655.35] "A"  MBMU,PC
 SG_ D2M_DCDCChrgeCrrnt_Limt_53 : 40|16@1+ (0.01,-500) [-500|155.35] "A"  MBMU,PC
 SG_ D2M_SUMDATA3_Reserved_53 : 56|8@1+ (1,0) [0|255] ""  MBMU,PC

BO_ 2333015926 D2M_SUMDATA3__54: 8 DCDC
 SG_ D2M_SUMDATA3_CRC_54 : 0|8@1+ (1,0) [0|255] ""  MBMU,PC
 SG_ D2M_DCDCLVPowerCurrent_54 : 8|8@1+ (0.1,0) [0|25.5] "A"  MBMU,PC
 SG_ D2M_DCDCLVPowerVoltage_54 : 16|8@1+ (0.2,0) [0|51] "V"  MBMU,PC
 SG_ D2M_DCDCDischrgCrrntLimt_54 : 24|16@1+ (0.01,0) [0|655.35] "A"  MBMU,PC
 SG_ D2M_DCDCChrgeCrrnt_Limt_54 : 40|16@1+ (0.01,-500) [-500|155.35] "A"  MBMU,PC
 SG_ D2M_SUMDATA3_Reserved_54 : 56|8@1+ (1,0) [0|255] ""  MBMU,PC

BO_ 2333015927 D2M_SUMDATA3__55: 8 DCDC
 SG_ D2M_SUMDATA3_CRC_55 : 0|8@1+ (1,0) [0|255] ""  MBMU,PC
 SG_ D2M_DCDCLVPowerCurrent_55 : 8|8@1+ (0.1,0) [0|25.5] "A"  MBMU,PC
 SG_ D2M_DCDCLVPowerVoltage_55 : 16|8@1+ (0.2,0) [0|51] "V"  MBMU,PC
 SG_ D2M_DCDCDischrgCrrntLimt_55 : 24|16@1+ (0.01,0) [0|655.35] "A"  MBMU,PC
 SG_ D2M_DCDCChrgeCrrnt_Limt_55 : 40|16@1+ (0.01,-500) [-500|155.35] "A"  MBMU,PC
 SG_ D2M_SUMDATA3_Reserved_55 : 56|8@1+ (1,0) [0|255] ""  MBMU,PC

BO_ 2333015928 D2M_SUMDATA3__56: 8 DCDC
 SG_ D2M_SUMDATA3_CRC_56 : 0|8@1+ (1,0) [0|255] ""  MBMU,PC
 SG_ D2M_DCDCLVPowerCurrent_56 : 8|8@1+ (0.1,0) [0|25.5] "A"  MBMU,PC
 SG_ D2M_DCDCLVPowerVoltage_56 : 16|8@1+ (0.2,0) [0|51] "V"  MBMU,PC
 SG_ D2M_DCDCDischrgCrrntLimt_56 : 24|16@1+ (0.01,0) [0|655.35] "A"  MBMU,PC
 SG_ D2M_DCDCChrgeCrrnt_Limt_56 : 40|16@1+ (0.01,-500) [-500|155.35] "A"  MBMU,PC
 SG_ D2M_SUMDATA3_Reserved_56 : 56|8@1+ (1,0) [0|255] ""  MBMU,PC

BO_ 2333015929 D2M_SUMDATA3__57: 8 DCDC
 SG_ D2M_SUMDATA3_CRC_57 : 0|8@1+ (1,0) [0|255] ""  MBMU,PC
 SG_ D2M_DCDCLVPowerCurrent_57 : 8|8@1+ (0.1,0) [0|25.5] "A"  MBMU,PC
 SG_ D2M_DCDCLVPowerVoltage_57 : 16|8@1+ (0.2,0) [0|51] "V"  MBMU,PC
 SG_ D2M_DCDCDischrgCrrntLimt_57 : 24|16@1+ (0.01,0) [0|655.35] "A"  MBMU,PC
 SG_ D2M_DCDCChrgeCrrnt_Limt_57 : 40|16@1+ (0.01,-500) [-500|155.35] "A"  MBMU,PC
 SG_ D2M_SUMDATA3_Reserved_57 : 56|8@1+ (1,0) [0|255] ""  MBMU,PC

BO_ 2333015930 D2M_SUMDATA3__58: 8 DCDC
 SG_ D2M_SUMDATA3_CRC_58 : 0|8@1+ (1,0) [0|255] ""  MBMU,PC
 SG_ D2M_DCDCLVPowerCurrent_58 : 8|8@1+ (0.1,0) [0|25.5] "A"  MBMU,PC
 SG_ D2M_DCDCLVPowerVoltage_58 : 16|8@1+ (0.2,0) [0|51] "V"  MBMU,PC
 SG_ D2M_DCDCDischrgCrrntLimt_58 : 24|16@1+ (0.01,0) [0|655.35] "A"  MBMU,PC
 SG_ D2M_DCDCChrgeCrrnt_Limt_58 : 40|16@1+ (0.01,-500) [-500|155.35] "A"  MBMU,PC
 SG_ D2M_SUMDATA3_Reserved_58 : 56|8@1+ (1,0) [0|255] ""  MBMU,PC

BO_ 2333015931 D2M_SUMDATA3__59: 8 DCDC
 SG_ D2M_SUMDATA3_CRC_59 : 0|8@1+ (1,0) [0|255] ""  MBMU,PC
 SG_ D2M_DCDCLVPowerCurrent_59 : 8|8@1+ (0.1,0) [0|25.5] "A"  MBMU,PC
 SG_ D2M_DCDCLVPowerVoltage_59 : 16|8@1+ (0.2,0) [0|51] "V"  MBMU,PC
 SG_ D2M_DCDCDischrgCrrntLimt_59 : 24|16@1+ (0.01,0) [0|655.35] "A"  MBMU,PC
 SG_ D2M_DCDCChrgeCrrnt_Limt_59 : 40|16@1+ (0.01,-500) [-500|155.35] "A"  MBMU,PC
 SG_ D2M_SUMDATA3_Reserved_59 : 56|8@1+ (1,0) [0|255] ""  MBMU,PC

BO_ 2333015932 D2M_SUMDATA3__60: 8 DCDC
 SG_ D2M_SUMDATA3_CRC_60 : 0|8@1+ (1,0) [0|255] ""  MBMU,PC
 SG_ D2M_DCDCLVPowerCurrent_60 : 8|8@1+ (0.1,0) [0|25.5] "A"  MBMU,PC
 SG_ D2M_DCDCLVPowerVoltage_60 : 16|8@1+ (0.2,0) [0|51] "V"  MBMU,PC
 SG_ D2M_DCDCDischrgCrrntLimt_60 : 24|16@1+ (0.01,0) [0|655.35] "A"  MBMU,PC
 SG_ D2M_DCDCChrgeCrrnt_Limt_60 : 40|16@1+ (0.01,-500) [-500|155.35] "A"  MBMU,PC
 SG_ D2M_SUMDATA3_Reserved_60 : 56|8@1+ (1,0) [0|255] ""  MBMU,PC

BO_ 2333015933 D2M_SUMDATA3__61: 8 DCDC
 SG_ D2M_SUMDATA3_CRC_61 : 0|8@1+ (1,0) [0|255] ""  MBMU,PC
 SG_ D2M_DCDCLVPowerCurrent_61 : 8|8@1+ (0.1,0) [0|25.5] "A"  MBMU,PC
 SG_ D2M_DCDCLVPowerVoltage_61 : 16|8@1+ (0.2,0) [0|51] "V"  MBMU,PC
 SG_ D2M_DCDCDischrgCrrntLimt_61 : 24|16@1+ (0.01,0) [0|655.35] "A"  MBMU,PC
 SG_ D2M_DCDCChrgeCrrnt_Limt_61 : 40|16@1+ (0.01,-500) [-500|155.35] "A"  MBMU,PC
 SG_ D2M_SUMDATA3_Reserved_61 : 56|8@1+ (1,0) [0|255] ""  MBMU,PC

BO_ 2333015934 D2M_SUMDATA3__62: 8 DCDC
 SG_ D2M_SUMDATA3_CRC_62 : 0|8@1+ (1,0) [0|255] ""  MBMU,PC
 SG_ D2M_DCDCLVPowerCurrent_62 : 8|8@1+ (0.1,0) [0|25.5] "A"  MBMU,PC
 SG_ D2M_DCDCLVPowerVoltage_62 : 16|8@1+ (0.2,0) [0|51] "V"  MBMU,PC
 SG_ D2M_DCDCDischrgCrrntLimt_62 : 24|16@1+ (0.01,0) [0|655.35] "A"  MBMU,PC
 SG_ D2M_DCDCChrgeCrrnt_Limt_62 : 40|16@1+ (0.01,-500) [-500|155.35] "A"  MBMU,PC
 SG_ D2M_SUMDATA3_Reserved_62 : 56|8@1+ (1,0) [0|255] ""  MBMU,PC

BO_ 2333015935 D2M_SUMDATA3__63: 8 DCDC
 SG_ D2M_SUMDATA3_CRC_63 : 0|8@1+ (1,0) [0|255] ""  MBMU,PC
 SG_ D2M_DCDCLVPowerCurrent_63 : 8|8@1+ (0.1,0) [0|25.5] "A"  MBMU,PC
 SG_ D2M_DCDCLVPowerVoltage_63 : 16|8@1+ (0.2,0) [0|51] "V"  MBMU,PC
 SG_ D2M_DCDCDischrgCrrntLimt_63 : 24|16@1+ (0.01,0) [0|655.35] "A"  MBMU,PC
 SG_ D2M_DCDCChrgeCrrnt_Limt_63 : 40|16@1+ (0.01,-500) [-500|155.35] "A"  MBMU,PC
 SG_ D2M_SUMDATA3_Reserved_63 : 56|8@1+ (1,0) [0|255] ""  MBMU,PC

BO_ 2333081409 D2M_SUMDATA4__01: 8 DCDC
 SG_ D2M_SUMDATA4_CRC_01 : 0|8@1+ (1,0) [0|255] ""  MBMU,PC
 SG_ D2M_DCDC_FaultCode_01 : 8|8@1+ (1,0) [0|255] ""  MBMU,PC
 SG_ D2M_DCDC_FaultClass_01 : 16|3@1+ (1,0) [0|7] ""  MBMU,PC
 SG_ D2M_DCDC_FaultNum_01 : 19|8@1+ (1,0) [0|255] ""  MBMU,PC
 SG_ D2M_SUMDATA4_Reserved_01 : 27|32@1+ (1,0) [0|4294967295] ""  MBMU,PC

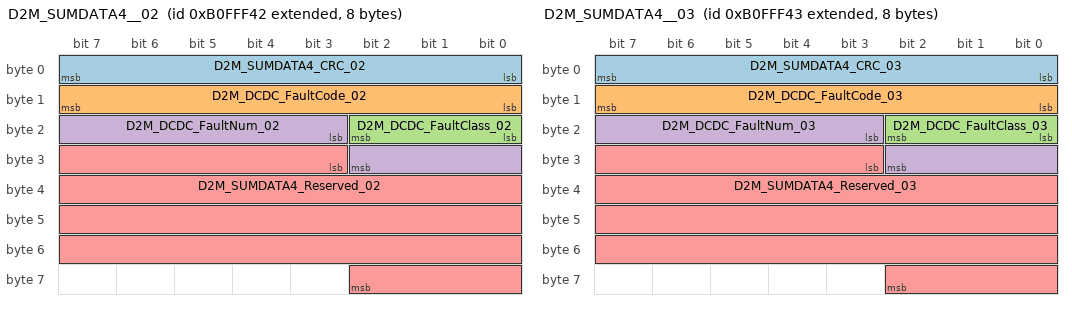
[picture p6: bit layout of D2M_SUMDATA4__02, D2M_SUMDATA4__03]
BO_ 2333081410 D2M_SUMDATA4__02: 8 DCDC
 SG_ D2M_SUMDATA4_CRC_02 : 0|8@1+ (1,0) [0|255] ""  MBMU,PC
 SG_ D2M_DCDC_FaultCode_02 : 8|8@1+ (1,0) [0|255] ""  MBMU,PC
 SG_ D2M_DCDC_FaultClass_02 : 16|3@1+ (1,0) [0|7] ""  MBMU,PC
 SG_ D2M_DCDC_FaultNum_02 : 19|8@1+ (1,0) [0|255] ""  MBMU,PC
 SG_ D2M_SUMDATA4_Reserved_02 : 27|32@1+ (1,0) [0|4294967295] ""  MBMU,PC

BO_ 2333081411 D2M_SUMDATA4__03: 8 DCDC
 SG_ D2M_SUMDATA4_CRC_03 : 0|8@1+ (1,0) [0|255] ""  MBMU,PC
 SG_ D2M_DCDC_FaultCode_03 : 8|8@1+ (1,0) [0|255] ""  MBMU,PC
 SG_ D2M_DCDC_FaultClass_03 : 16|3@1+ (1,0) [0|7] ""  MBMU,PC
 SG_ D2M_DCDC_FaultNum_03 : 19|8@1+ (1,0) [0|255] ""  MBMU,PC
 SG_ D2M_SUMDATA4_Reserved_03 : 27|32@1+ (1,0) [0|4294967295] ""  MBMU,PC

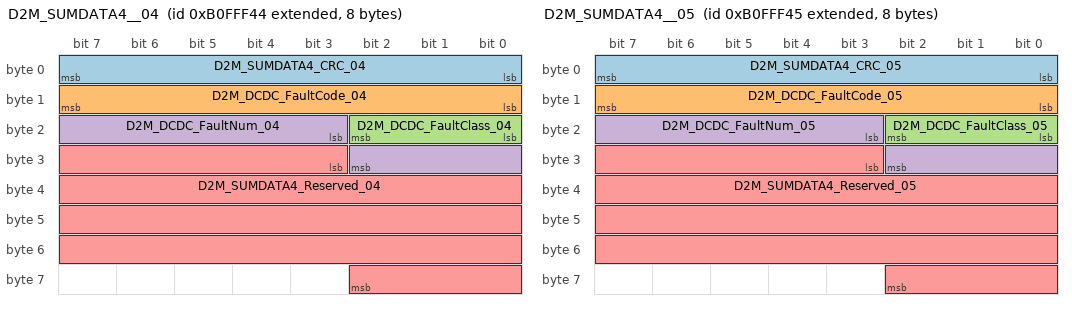
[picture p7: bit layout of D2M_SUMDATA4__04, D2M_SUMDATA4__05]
BO_ 2333081412 D2M_SUMDATA4__04: 8 DCDC
 SG_ D2M_SUMDATA4_CRC_04 : 0|8@1+ (1,0) [0|255] ""  MBMU,PC
 SG_ D2M_DCDC_FaultCode_04 : 8|8@1+ (1,0) [0|255] ""  MBMU,PC
 SG_ D2M_DCDC_FaultClass_04 : 16|3@1+ (1,0) [0|7] ""  MBMU,PC
 SG_ D2M_DCDC_FaultNum_04 : 19|8@1+ (1,0) [0|255] ""  MBMU,PC
 SG_ D2M_SUMDATA4_Reserved_04 : 27|32@1+ (1,0) [0|4294967295] ""  MBMU,PC

BO_ 2333081413 D2M_SUMDATA4__05: 8 DCDC
 SG_ D2M_SUMDATA4_CRC_05 : 0|8@1+ (1,0) [0|255] ""  MBMU,PC
 SG_ D2M_DCDC_FaultCode_05 : 8|8@1+ (1,0) [0|255] ""  MBMU,PC
 SG_ D2M_DCDC_FaultClass_05 : 16|3@1+ (1,0) [0|7] ""  MBMU,PC
 SG_ D2M_DCDC_FaultNum_05 : 19|8@1+ (1,0) [0|255] ""  MBMU,PC
 SG_ D2M_SUMDATA4_Reserved_05 : 27|32@1+ (1,0) [0|4294967295] ""  MBMU,PC

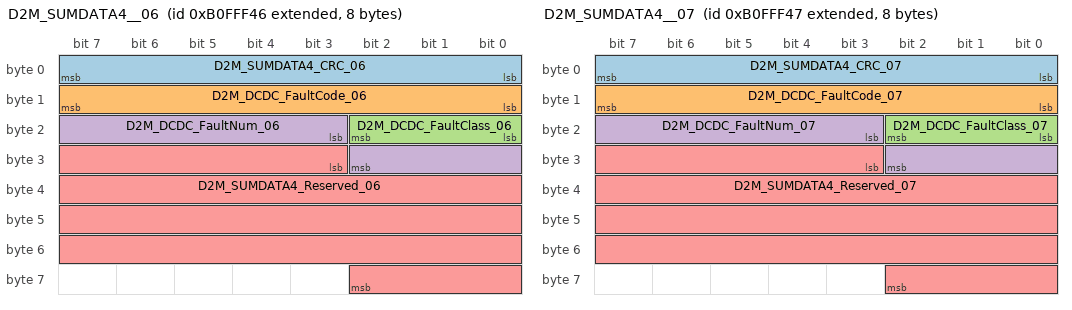
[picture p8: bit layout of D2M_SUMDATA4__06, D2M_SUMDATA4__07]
BO_ 2333081414 D2M_SUMDATA4__06: 8 DCDC
 SG_ D2M_SUMDATA4_CRC_06 : 0|8@1+ (1,0) [0|255] ""  MBMU,PC
 SG_ D2M_DCDC_FaultCode_06 : 8|8@1+ (1,0) [0|255] ""  MBMU,PC
 SG_ D2M_DCDC_FaultClass_06 : 16|3@1+ (1,0) [0|7] ""  MBMU,PC
 SG_ D2M_DCDC_FaultNum_06 : 19|8@1+ (1,0) [0|255] ""  MBMU,PC
 SG_ D2M_SUMDATA4_Reserved_06 : 27|32@1+ (1,0) [0|4294967295] ""  MBMU,PC

BO_ 2333081415 D2M_SUMDATA4__07: 8 DCDC
 SG_ D2M_SUMDATA4_CRC_07 : 0|8@1+ (1,0) [0|255] ""  MBMU,PC
 SG_ D2M_DCDC_FaultCode_07 : 8|8@1+ (1,0) [0|255] ""  MBMU,PC
 SG_ D2M_DCDC_FaultClass_07 : 16|3@1+ (1,0) [0|7] ""  MBMU,PC
 SG_ D2M_DCDC_FaultNum_07 : 19|8@1+ (1,0) [0|255] ""  MBMU,PC
 SG_ D2M_SUMDATA4_Reserved_07 : 27|32@1+ (1,0) [0|4294967295] ""  MBMU,PC

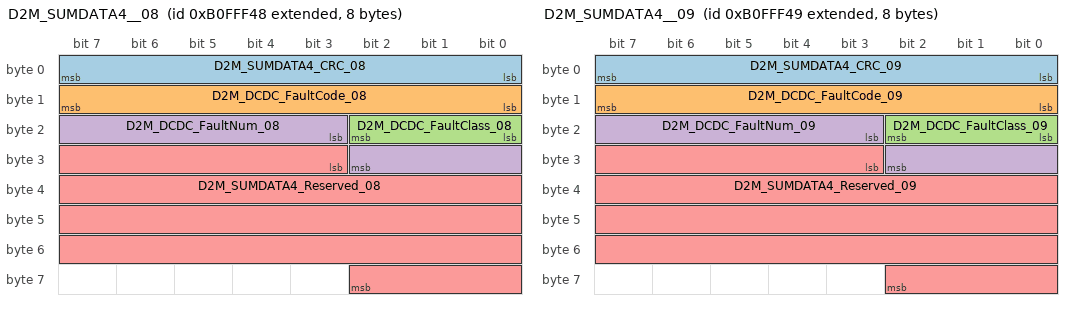
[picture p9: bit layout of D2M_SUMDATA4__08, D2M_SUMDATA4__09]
BO_ 2333081416 D2M_SUMDATA4__08: 8 DCDC
 SG_ D2M_SUMDATA4_CRC_08 : 0|8@1+ (1,0) [0|255] ""  MBMU,PC
 SG_ D2M_DCDC_FaultCode_08 : 8|8@1+ (1,0) [0|255] ""  MBMU,PC
 SG_ D2M_DCDC_FaultClass_08 : 16|3@1+ (1,0) [0|7] ""  MBMU,PC
 SG_ D2M_DCDC_FaultNum_08 : 19|8@1+ (1,0) [0|255] ""  MBMU,PC
 SG_ D2M_SUMDATA4_Reserved_08 : 27|32@1+ (1,0) [0|4294967295] ""  MBMU,PC

BO_ 2333081417 D2M_SUMDATA4__09: 8 DCDC
 SG_ D2M_SUMDATA4_CRC_09 : 0|8@1+ (1,0) [0|255] ""  MBMU,PC
 SG_ D2M_DCDC_FaultCode_09 : 8|8@1+ (1,0) [0|255] ""  MBMU,PC
 SG_ D2M_DCDC_FaultClass_09 : 16|3@1+ (1,0) [0|7] ""  MBMU,PC
 SG_ D2M_DCDC_FaultNum_09 : 19|8@1+ (1,0) [0|255] ""  MBMU,PC
 SG_ D2M_SUMDATA4_Reserved_09 : 27|32@1+ (1,0) [0|4294967295] ""  MBMU,PC

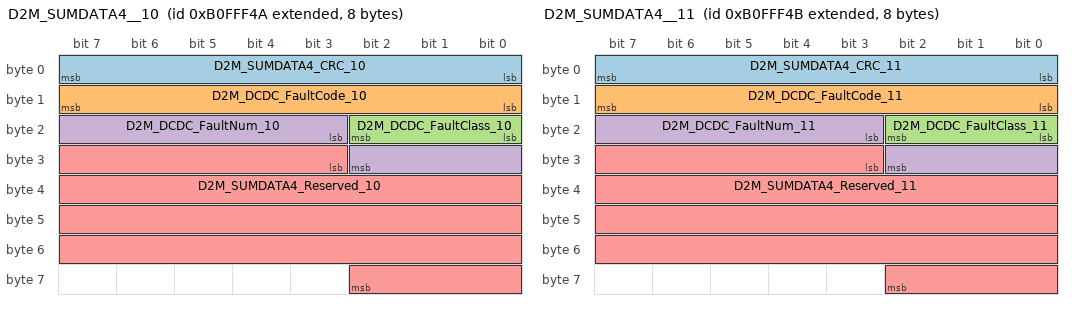
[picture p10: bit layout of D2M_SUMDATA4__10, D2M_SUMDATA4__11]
BO_ 2333081418 D2M_SUMDATA4__10: 8 DCDC
 SG_ D2M_SUMDATA4_CRC_10 : 0|8@1+ (1,0) [0|255] ""  MBMU,PC
 SG_ D2M_DCDC_FaultCode_10 : 8|8@1+ (1,0) [0|255] ""  MBMU,PC
 SG_ D2M_DCDC_FaultClass_10 : 16|3@1+ (1,0) [0|7] ""  MBMU,PC
 SG_ D2M_DCDC_FaultNum_10 : 19|8@1+ (1,0) [0|255] ""  MBMU,PC
 SG_ D2M_SUMDATA4_Reserved_10 : 27|32@1+ (1,0) [0|4294967295] ""  MBMU,PC

BO_ 2333081419 D2M_SUMDATA4__11: 8 DCDC
 SG_ D2M_SUMDATA4_CRC_11 : 0|8@1+ (1,0) [0|255] ""  MBMU,PC
 SG_ D2M_DCDC_FaultCode_11 : 8|8@1+ (1,0) [0|255] ""  MBMU,PC
 SG_ D2M_DCDC_FaultClass_11 : 16|3@1+ (1,0) [0|7] ""  MBMU,PC
 SG_ D2M_DCDC_FaultNum_11 : 19|8@1+ (1,0) [0|255] ""  MBMU,PC
 SG_ D2M_SUMDATA4_Reserved_11 : 27|32@1+ (1,0) [0|4294967295] ""  MBMU,PC

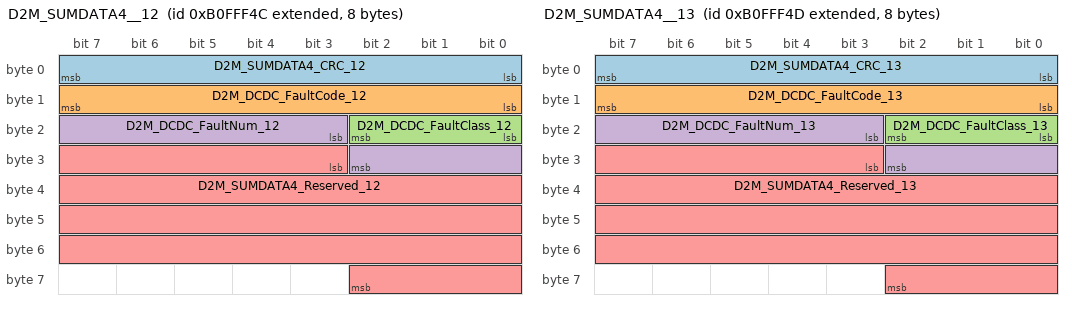
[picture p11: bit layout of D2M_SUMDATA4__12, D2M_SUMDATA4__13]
BO_ 2333081420 D2M_SUMDATA4__12: 8 DCDC
 SG_ D2M_SUMDATA4_CRC_12 : 0|8@1+ (1,0) [0|255] ""  MBMU,PC
 SG_ D2M_DCDC_FaultCode_12 : 8|8@1+ (1,0) [0|255] ""  MBMU,PC
 SG_ D2M_DCDC_FaultClass_12 : 16|3@1+ (1,0) [0|7] ""  MBMU,PC
 SG_ D2M_DCDC_FaultNum_12 : 19|8@1+ (1,0) [0|255] ""  MBMU,PC
 SG_ D2M_SUMDATA4_Reserved_12 : 27|32@1+ (1,0) [0|4294967295] ""  MBMU,PC

BO_ 2333081421 D2M_SUMDATA4__13: 8 DCDC
 SG_ D2M_SUMDATA4_CRC_13 : 0|8@1+ (1,0) [0|255] ""  MBMU,PC
 SG_ D2M_DCDC_FaultCode_13 : 8|8@1+ (1,0) [0|255] ""  MBMU,PC
 SG_ D2M_DCDC_FaultClass_13 : 16|3@1+ (1,0) [0|7] ""  MBMU,PC
 SG_ D2M_DCDC_FaultNum_13 : 19|8@1+ (1,0) [0|255] ""  MBMU,PC
 SG_ D2M_SUMDATA4_Reserved_13 : 27|32@1+ (1,0) [0|4294967295] ""  MBMU,PC

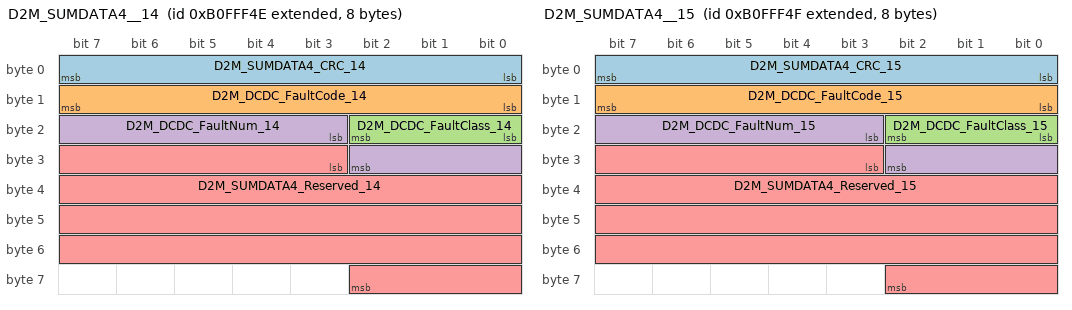
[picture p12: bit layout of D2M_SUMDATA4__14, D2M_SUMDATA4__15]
BO_ 2333081422 D2M_SUMDATA4__14: 8 DCDC
 SG_ D2M_SUMDATA4_CRC_14 : 0|8@1+ (1,0) [0|255] ""  MBMU,PC
 SG_ D2M_DCDC_FaultCode_14 : 8|8@1+ (1,0) [0|255] ""  MBMU,PC
 SG_ D2M_DCDC_FaultClass_14 : 16|3@1+ (1,0) [0|7] ""  MBMU,PC
 SG_ D2M_DCDC_FaultNum_14 : 19|8@1+ (1,0) [0|255] ""  MBMU,PC
 SG_ D2M_SUMDATA4_Reserved_14 : 27|32@1+ (1,0) [0|4294967295] ""  MBMU,PC

BO_ 2333081423 D2M_SUMDATA4__15: 8 DCDC
 SG_ D2M_SUMDATA4_CRC_15 : 0|8@1+ (1,0) [0|255] ""  MBMU,PC
 SG_ D2M_DCDC_FaultCode_15 : 8|8@1+ (1,0) [0|255] ""  MBMU,PC
 SG_ D2M_DCDC_FaultClass_15 : 16|3@1+ (1,0) [0|7] ""  MBMU,PC
 SG_ D2M_DCDC_FaultNum_15 : 19|8@1+ (1,0) [0|255] ""  MBMU,PC
 SG_ D2M_SUMDATA4_Reserved_15 : 27|32@1+ (1,0) [0|4294967295] ""  MBMU,PC

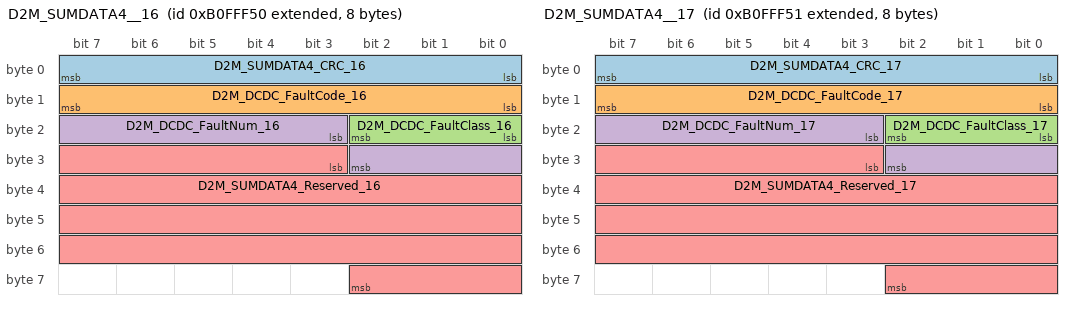
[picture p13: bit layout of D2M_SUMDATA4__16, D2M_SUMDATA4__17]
BO_ 2333081424 D2M_SUMDATA4__16: 8 DCDC
 SG_ D2M_SUMDATA4_CRC_16 : 0|8@1+ (1,0) [0|255] ""  MBMU,PC
 SG_ D2M_DCDC_FaultCode_16 : 8|8@1+ (1,0) [0|255] ""  MBMU,PC
 SG_ D2M_DCDC_FaultClass_16 : 16|3@1+ (1,0) [0|7] ""  MBMU,PC
 SG_ D2M_DCDC_FaultNum_16 : 19|8@1+ (1,0) [0|255] ""  MBMU,PC
 SG_ D2M_SUMDATA4_Reserved_16 : 27|32@1+ (1,0) [0|4294967295] ""  MBMU,PC

BO_ 2333081425 D2M_SUMDATA4__17: 8 DCDC
 SG_ D2M_SUMDATA4_CRC_17 : 0|8@1+ (1,0) [0|255] ""  MBMU,PC
 SG_ D2M_DCDC_FaultCode_17 : 8|8@1+ (1,0) [0|255] ""  MBMU,PC
 SG_ D2M_DCDC_FaultClass_17 : 16|3@1+ (1,0) [0|7] ""  MBMU,PC
 SG_ D2M_DCDC_FaultNum_17 : 19|8@1+ (1,0) [0|255] ""  MBMU,PC
 SG_ D2M_SUMDATA4_Reserved_17 : 27|32@1+ (1,0) [0|4294967295] ""  MBMU,PC

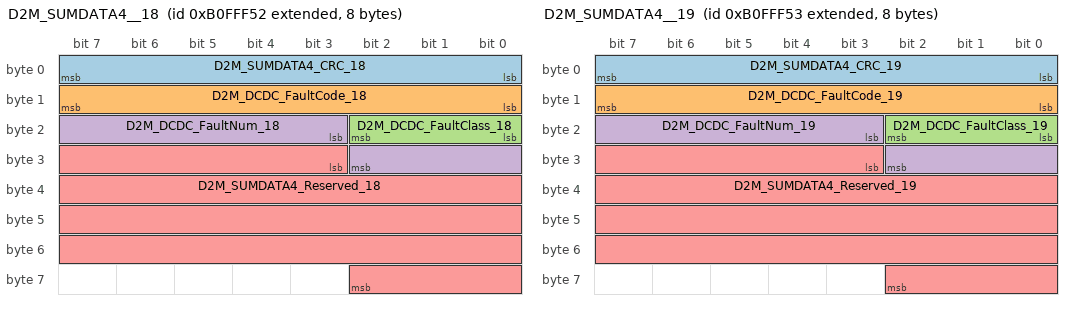
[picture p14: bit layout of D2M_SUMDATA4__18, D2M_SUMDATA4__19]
BO_ 2333081426 D2M_SUMDATA4__18: 8 DCDC
 SG_ D2M_SUMDATA4_CRC_18 : 0|8@1+ (1,0) [0|255] ""  MBMU,PC
 SG_ D2M_DCDC_FaultCode_18 : 8|8@1+ (1,0) [0|255] ""  MBMU,PC
 SG_ D2M_DCDC_FaultClass_18 : 16|3@1+ (1,0) [0|7] ""  MBMU,PC
 SG_ D2M_DCDC_FaultNum_18 : 19|8@1+ (1,0) [0|255] ""  MBMU,PC
 SG_ D2M_SUMDATA4_Reserved_18 : 27|32@1+ (1,0) [0|4294967295] ""  MBMU,PC

BO_ 2333081427 D2M_SUMDATA4__19: 8 DCDC
 SG_ D2M_SUMDATA4_CRC_19 : 0|8@1+ (1,0) [0|255] ""  MBMU,PC
 SG_ D2M_DCDC_FaultCode_19 : 8|8@1+ (1,0) [0|255] ""  MBMU,PC
 SG_ D2M_DCDC_FaultClass_19 : 16|3@1+ (1,0) [0|7] ""  MBMU,PC
 SG_ D2M_DCDC_FaultNum_19 : 19|8@1+ (1,0) [0|255] ""  MBMU,PC
 SG_ D2M_SUMDATA4_Reserved_19 : 27|32@1+ (1,0) [0|4294967295] ""  MBMU,PC

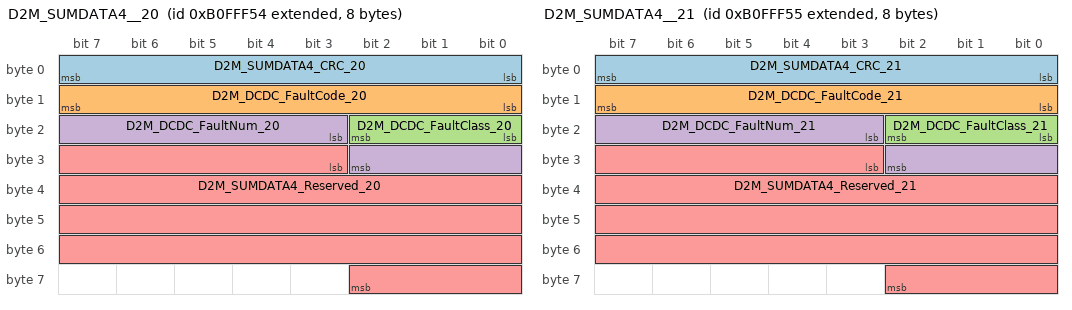
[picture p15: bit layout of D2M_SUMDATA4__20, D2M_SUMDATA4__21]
BO_ 2333081428 D2M_SUMDATA4__20: 8 DCDC
 SG_ D2M_SUMDATA4_CRC_20 : 0|8@1+ (1,0) [0|255] ""  MBMU,PC
 SG_ D2M_DCDC_FaultCode_20 : 8|8@1+ (1,0) [0|255] ""  MBMU,PC
 SG_ D2M_DCDC_FaultClass_20 : 16|3@1+ (1,0) [0|7] ""  MBMU,PC
 SG_ D2M_DCDC_FaultNum_20 : 19|8@1+ (1,0) [0|255] ""  MBMU,PC
 SG_ D2M_SUMDATA4_Reserved_20 : 27|32@1+ (1,0) [0|4294967295] ""  MBMU,PC

BO_ 2333081429 D2M_SUMDATA4__21: 8 DCDC
 SG_ D2M_SUMDATA4_CRC_21 : 0|8@1+ (1,0) [0|255] ""  MBMU,PC
 SG_ D2M_DCDC_FaultCode_21 : 8|8@1+ (1,0) [0|255] ""  MBMU,PC
 SG_ D2M_DCDC_FaultClass_21 : 16|3@1+ (1,0) [0|7] ""  MBMU,PC
 SG_ D2M_DCDC_FaultNum_21 : 19|8@1+ (1,0) [0|255] ""  MBMU,PC
 SG_ D2M_SUMDATA4_Reserved_21 : 27|32@1+ (1,0) [0|4294967295] ""  MBMU,PC

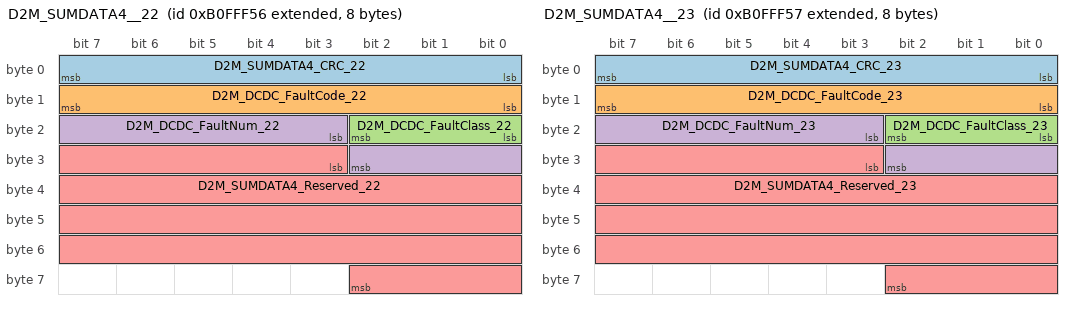
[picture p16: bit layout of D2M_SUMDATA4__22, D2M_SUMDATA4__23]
BO_ 2333081430 D2M_SUMDATA4__22: 8 DCDC
 SG_ D2M_SUMDATA4_CRC_22 : 0|8@1+ (1,0) [0|255] ""  MBMU,PC
 SG_ D2M_DCDC_FaultCode_22 : 8|8@1+ (1,0) [0|255] ""  MBMU,PC
 SG_ D2M_DCDC_FaultClass_22 : 16|3@1+ (1,0) [0|7] ""  MBMU,PC
 SG_ D2M_DCDC_FaultNum_22 : 19|8@1+ (1,0) [0|255] ""  MBMU,PC
 SG_ D2M_SUMDATA4_Reserved_22 : 27|32@1+ (1,0) [0|4294967295] ""  MBMU,PC

BO_ 2333081431 D2M_SUMDATA4__23: 8 DCDC
 SG_ D2M_SUMDATA4_CRC_23 : 0|8@1+ (1,0) [0|255] ""  MBMU,PC
 SG_ D2M_DCDC_FaultCode_23 : 8|8@1+ (1,0) [0|255] ""  MBMU,PC
 SG_ D2M_DCDC_FaultClass_23 : 16|3@1+ (1,0) [0|7] ""  MBMU,PC
 SG_ D2M_DCDC_FaultNum_23 : 19|8@1+ (1,0) [0|255] ""  MBMU,PC
 SG_ D2M_SUMDATA4_Reserved_23 : 27|32@1+ (1,0) [0|4294967295] ""  MBMU,PC

BO_ 2333081432 D2M_SUMDATA4__24: 8 DCDC
 SG_ D2M_SUMDATA4_CRC_24 : 0|8@1+ (1,0) [0|255] ""  MBMU,PC
 SG_ D2M_DCDC_FaultCode_24 : 8|8@1+ (1,0) [0|255] ""  MBMU,PC
 SG_ D2M_DCDC_FaultClass_24 : 16|3@1+ (1,0) [0|7] ""  MBMU,PC
 SG_ D2M_DCDC_FaultNum_24 : 19|8@1+ (1,0) [0|255] ""  MBMU,PC
 SG_ D2M_SUMDATA4_Reserved_24 : 27|32@1+ (1,0) [0|4294967295] ""  MBMU,PC

BO_ 2333081433 D2M_SUMDATA4__25: 8 DCDC
 SG_ D2M_SUMDATA4_CRC_25 : 0|8@1+ (1,0) [0|255] ""  MBMU,PC
 SG_ D2M_DCDC_FaultCode_25 : 8|8@1+ (1,0) [0|255] ""  MBMU,PC
 SG_ D2M_DCDC_FaultClass_25 : 16|3@1+ (1,0) [0|7] ""  MBMU,PC
 SG_ D2M_DCDC_FaultNum_25 : 19|8@1+ (1,0) [0|255] ""  MBMU,PC
 SG_ D2M_SUMDATA4_Reserved_25 : 27|32@1+ (1,0) [0|4294967295] ""  MBMU,PC

BO_ 2333081434 D2M_SUMDATA4__26: 8 DCDC
 SG_ D2M_SUMDATA4_CRC_26 : 0|8@1+ (1,0) [0|255] ""  MBMU,PC
 SG_ D2M_DCDC_FaultCode_26 : 8|8@1+ (1,0) [0|255] ""  MBMU,PC
 SG_ D2M_DCDC_FaultClass_26 : 16|3@1+ (1,0) [0|7] ""  MBMU,PC
 SG_ D2M_DCDC_FaultNum_26 : 19|8@1+ (1,0) [0|255] ""  MBMU,PC
 SG_ D2M_SUMDATA4_Reserved_26 : 27|32@1+ (1,0) [0|4294967295] ""  MBMU,PC

BO_ 2333081435 D2M_SUMDATA4__27: 8 DCDC
 SG_ D2M_SUMDATA4_CRC_27 : 0|8@1+ (1,0) [0|255] ""  MBMU,PC
 SG_ D2M_DCDC_FaultCode_27 : 8|8@1+ (1,0) [0|255] ""  MBMU,PC
 SG_ D2M_DCDC_FaultClass_27 : 16|3@1+ (1,0) [0|7] ""  MBMU,PC
 SG_ D2M_DCDC_FaultNum_27 : 19|8@1+ (1,0) [0|255] ""  MBMU,PC
 SG_ D2M_SUMDATA4_Reserved_27 : 27|32@1+ (1,0) [0|4294967295] ""  MBMU,PC

BO_ 2333081436 D2M_SUMDATA4__28: 8 DCDC
 SG_ D2M_SUMDATA4_CRC_28 : 0|8@1+ (1,0) [0|255] ""  MBMU,PC
 SG_ D2M_DCDC_FaultCode_28 : 8|8@1+ (1,0) [0|255] ""  MBMU,PC
 SG_ D2M_DCDC_FaultClass_28 : 16|3@1+ (1,0) [0|7] ""  MBMU,PC
 SG_ D2M_DCDC_FaultNum_28 : 19|8@1+ (1,0) [0|255] ""  MBMU,PC
 SG_ D2M_SUMDATA4_Reserved_28 : 27|32@1+ (1,0) [0|4294967295] ""  MBMU,PC

BO_ 2333081437 D2M_SUMDATA4__29: 8 DCDC
 SG_ D2M_SUMDATA4_CRC_29 : 0|8@1+ (1,0) [0|255] ""  MBMU,PC
 SG_ D2M_DCDC_FaultCode_29 : 8|8@1+ (1,0) [0|255] ""  MBMU,PC
 SG_ D2M_DCDC_FaultClass_29 : 16|3@1+ (1,0) [0|7] ""  MBMU,PC
 SG_ D2M_DCDC_FaultNum_29 : 19|8@1+ (1,0) [0|255] ""  MBMU,PC
 SG_ D2M_SUMDATA4_Reserved_29 : 27|32@1+ (1,0) [0|4294967295] ""  MBMU,PC

BO_ 2333081438 D2M_SUMDATA4__30: 8 DCDC
 SG_ D2M_SUMDATA4_CRC_30 : 0|8@1+ (1,0) [0|255] ""  MBMU,PC
 SG_ D2M_DCDC_FaultCode_30 : 8|8@1+ (1,0) [0|255] ""  MBMU,PC
 SG_ D2M_DCDC_FaultClass_30 : 16|3@1+ (1,0) [0|7] ""  MBMU,PC
 SG_ D2M_DCDC_FaultNum_30 : 19|8@1+ (1,0) [0|255] ""  MBMU,PC
 SG_ D2M_SUMDATA4_Reserved_30 : 27|32@1+ (1,0) [0|4294967295] ""  MBMU,PC

BO_ 2333081439 D2M_SUMDATA4__31: 8 DCDC
 SG_ D2M_SUMDATA4_CRC_31 : 0|8@1+ (1,0) [0|255] ""  MBMU,PC
 SG_ D2M_DCDC_FaultCode_31 : 8|8@1+ (1,0) [0|255] ""  MBMU,PC
 SG_ D2M_DCDC_FaultClass_31 : 16|3@1+ (1,0) [0|7] ""  MBMU,PC
 SG_ D2M_DCDC_FaultNum_31 : 19|8@1+ (1,0) [0|255] ""  MBMU,PC
 SG_ D2M_SUMDATA4_Reserved_31 : 27|32@1+ (1,0) [0|4294967295] ""  MBMU,PC

BO_ 2333081440 D2M_SUMDATA4__32: 8 DCDC
 SG_ D2M_SUMDATA4_CRC_32 : 0|8@1+ (1,0) [0|255] ""  MBMU,PC
 SG_ D2M_DCDC_FaultCode_32 : 8|8@1+ (1,0) [0|255] ""  MBMU,PC
 SG_ D2M_DCDC_FaultClass_32 : 16|3@1+ (1,0) [0|7] ""  MBMU,PC
 SG_ D2M_DCDC_FaultNum_32 : 19|8@1+ (1,0) [0|255] ""  MBMU,PC
 SG_ D2M_SUMDATA4_Reserved_32 : 27|32@1+ (1,0) [0|4294967295] ""  MBMU,PC

BO_ 2333081441 D2M_SUMDATA4__33: 8 DCDC
 SG_ D2M_SUMDATA4_CRC_33 : 0|8@1+ (1,0) [0|255] ""  MBMU,PC
 SG_ D2M_DCDC_FaultCode_33 : 8|8@1+ (1,0) [0|255] ""  MBMU,PC
 SG_ D2M_DCDC_FaultClass_33 : 16|3@1+ (1,0) [0|7] ""  MBMU,PC
 SG_ D2M_DCDC_FaultNum_33 : 19|8@1+ (1,0) [0|255] ""  MBMU,PC
 SG_ D2M_SUMDATA4_Reserved_33 : 27|32@1+ (1,0) [0|4294967295] ""  MBMU,PC

BO_ 2333081442 D2M_SUMDATA4__34: 8 DCDC
 SG_ D2M_SUMDATA4_CRC_34 : 0|8@1+ (1,0) [0|255] ""  MBMU,PC
 SG_ D2M_DCDC_FaultCode_34 : 8|8@1+ (1,0) [0|255] ""  MBMU,PC
 SG_ D2M_DCDC_FaultClass_34 : 16|3@1+ (1,0) [0|7] ""  MBMU,PC
 SG_ D2M_DCDC_FaultNum_34 : 19|8@1+ (1,0) [0|255] ""  MBMU,PC
 SG_ D2M_SUMDATA4_Reserved_34 : 27|32@1+ (1,0) [0|4294967295] ""  MBMU,PC

BO_ 2333081443 D2M_SUMDATA4__35: 8 DCDC
 SG_ D2M_SUMDATA4_CRC_35 : 0|8@1+ (1,0) [0|255] ""  MBMU,PC
 SG_ D2M_DCDC_FaultCode_35 : 8|8@1+ (1,0) [0|255] ""  MBMU,PC
 SG_ D2M_DCDC_FaultClass_35 : 16|3@1+ (1,0) [0|7] ""  MBMU,PC
 SG_ D2M_DCDC_FaultNum_35 : 19|8@1+ (1,0) [0|255] ""  MBMU,PC
 SG_ D2M_SUMDATA4_Reserved_35 : 27|32@1+ (1,0) [0|4294967295] ""  MBMU,PC

BO_ 2333081444 D2M_SUMDATA4__36: 8 DCDC
 SG_ D2M_SUMDATA4_CRC_36 : 0|8@1+ (1,0) [0|255] ""  MBMU,PC
 SG_ D2M_DCDC_FaultCode_36 : 8|8@1+ (1,0) [0|255] ""  MBMU,PC
 SG_ D2M_DCDC_FaultClass_36 : 16|3@1+ (1,0) [0|7] ""  MBMU,PC
 SG_ D2M_DCDC_FaultNum_36 : 19|8@1+ (1,0) [0|255] ""  MBMU,PC
 SG_ D2M_SUMDATA4_Reserved_36 : 27|32@1+ (1,0) [0|4294967295] ""  MBMU,PC

BO_ 2333081445 D2M_SUMDATA4__37: 8 DCDC
 SG_ D2M_SUMDATA4_CRC_37 : 0|8@1+ (1,0) [0|255] ""  MBMU,PC
 SG_ D2M_DCDC_FaultCode_37 : 8|8@1+ (1,0) [0|255] ""  MBMU,PC
 SG_ D2M_DCDC_FaultClass_37 : 16|3@1+ (1,0) [0|7] ""  MBMU,PC
 SG_ D2M_DCDC_FaultNum_37 : 19|8@1+ (1,0) [0|255] ""  MBMU,PC
 SG_ D2M_SUMDATA4_Reserved_37 : 27|32@1+ (1,0) [0|4294967295] ""  MBMU,PC

BO_ 2333081446 D2M_SUMDATA4__38: 8 DCDC
 SG_ D2M_SUMDATA4_CRC_38 : 0|8@1+ (1,0) [0|255] ""  MBMU,PC
 SG_ D2M_DCDC_FaultCode_38 : 8|8@1+ (1,0) [0|255] ""  MBMU,PC
 SG_ D2M_DCDC_FaultClass_38 : 16|3@1+ (1,0) [0|7] ""  MBMU,PC
 SG_ D2M_DCDC_FaultNum_38 : 19|8@1+ (1,0) [0|255] ""  MBMU,PC
 SG_ D2M_SUMDATA4_Reserved_38 : 27|32@1+ (1,0) [0|4294967295] ""  MBMU,PC

BO_ 2333081447 D2M_SUMDATA4__39: 8 DCDC
 SG_ D2M_SUMDATA4_CRC_39 : 0|8@1+ (1,0) [0|255] ""  MBMU,PC
 SG_ D2M_DCDC_FaultCode_39 : 8|8@1+ (1,0) [0|255] ""  MBMU,PC
 SG_ D2M_DCDC_FaultClass_39 : 16|3@1+ (1,0) [0|7] ""  MBMU,PC
 SG_ D2M_DCDC_FaultNum_39 : 19|8@1+ (1,0) [0|255] ""  MBMU,PC
 SG_ D2M_SUMDATA4_Reserved_39 : 27|32@1+ (1,0) [0|4294967295] ""  MBMU,PC

BO_ 2333081448 D2M_SUMDATA4__40: 8 DCDC
 SG_ D2M_SUMDATA4_CRC_40 : 0|8@1+ (1,0) [0|255] ""  MBMU,PC
 SG_ D2M_DCDC_FaultCode_40 : 8|8@1+ (1,0) [0|255] ""  MBMU,PC
 SG_ D2M_DCDC_FaultClass_40 : 16|3@1+ (1,0) [0|7] ""  MBMU,PC
 SG_ D2M_DCDC_FaultNum_40 : 19|8@1+ (1,0) [0|255] ""  MBMU,PC
 SG_ D2M_SUMDATA4_Reserved_40 : 27|32@1+ (1,0) [0|4294967295] ""  MBMU,PC

BO_ 2333081449 D2M_SUMDATA4__41: 8 DCDC
 SG_ D2M_SUMDATA4_CRC_41 : 0|8@1+ (1,0) [0|255] ""  MBMU,PC
 SG_ D2M_DCDC_FaultCode_41 : 8|8@1+ (1,0) [0|255] ""  MBMU,PC
 SG_ D2M_DCDC_FaultClass_41 : 16|3@1+ (1,0) [0|7] ""  MBMU,PC
 SG_ D2M_DCDC_FaultNum_41 : 19|8@1+ (1,0) [0|255] ""  MBMU,PC
 SG_ D2M_SUMDATA4_Reserved_41 : 27|32@1+ (1,0) [0|4294967295] ""  MBMU,PC

BO_ 2333081450 D2M_SUMDATA4__42: 8 DCDC
 SG_ D2M_SUMDATA4_CRC_42 : 0|8@1+ (1,0) [0|255] ""  MBMU,PC
 SG_ D2M_DCDC_FaultCode_42 : 8|8@1+ (1,0) [0|255] ""  MBMU,PC
 SG_ D2M_DCDC_FaultClass_42 : 16|3@1+ (1,0) [0|7] ""  MBMU,PC
 SG_ D2M_DCDC_FaultNum_42 : 19|8@1+ (1,0) [0|255] ""  MBMU,PC
 SG_ D2M_SUMDATA4_Reserved_42 : 27|32@1+ (1,0) [0|4294967295] ""  MBMU,PC

BO_ 2333081451 D2M_SUMDATA4__43: 8 DCDC
 SG_ D2M_SUMDATA4_CRC_43 : 0|8@1+ (1,0) [0|255] ""  MBMU,PC
 SG_ D2M_DCDC_FaultCode_43 : 8|8@1+ (1,0) [0|255] ""  MBMU,PC
 SG_ D2M_DCDC_FaultClass_43 : 16|3@1+ (1,0) [0|7] ""  MBMU,PC
 SG_ D2M_DCDC_FaultNum_43 : 19|8@1+ (1,0) [0|255] ""  MBMU,PC
 SG_ D2M_SUMDATA4_Reserved_43 : 27|32@1+ (1,0) [0|4294967295] ""  MBMU,PC

BO_ 2333081452 D2M_SUMDATA4__44: 8 DCDC
 SG_ D2M_SUMDATA4_CRC_44 : 0|8@1+ (1,0) [0|255] ""  MBMU,PC
 SG_ D2M_DCDC_FaultCode_44 : 8|8@1+ (1,0) [0|255] ""  MBMU,PC
 SG_ D2M_DCDC_FaultClass_44 : 16|3@1+ (1,0) [0|7] ""  MBMU,PC
 SG_ D2M_DCDC_FaultNum_44 : 19|8@1+ (1,0) [0|255] ""  MBMU,PC
 SG_ D2M_SUMDATA4_Reserved_44 : 27|32@1+ (1,0) [0|4294967295] ""  MBMU,PC

BO_ 2333081453 D2M_SUMDATA4__45: 8 DCDC
 SG_ D2M_SUMDATA4_CRC_45 : 0|8@1+ (1,0) [0|255] ""  MBMU,PC
 SG_ D2M_DCDC_FaultCode_45 : 8|8@1+ (1,0) [0|255] ""  MBMU,PC
 SG_ D2M_DCDC_FaultClass_45 : 16|3@1+ (1,0) [0|7] ""  MBMU,PC
 SG_ D2M_DCDC_FaultNum_45 : 19|8@1+ (1,0) [0|255] ""  MBMU,PC
 SG_ D2M_SUMDATA4_Reserved_45 : 27|32@1+ (1,0) [0|4294967295] ""  MBMU,PC

BO_ 2333081454 D2M_SUMDATA4__46: 8 DCDC
 SG_ D2M_SUMDATA4_CRC_46 : 0|8@1+ (1,0) [0|255] ""  MBMU,PC
 SG_ D2M_DCDC_FaultCode_46 : 8|8@1+ (1,0) [0|255] ""  MBMU,PC
 SG_ D2M_DCDC_FaultClass_46 : 16|3@1+ (1,0) [0|7] ""  MBMU,PC
 SG_ D2M_DCDC_FaultNum_46 : 19|8@1+ (1,0) [0|255] ""  MBMU,PC
 SG_ D2M_SUMDATA4_Reserved_46 : 27|32@1+ (1,0) [0|4294967295] ""  MBMU,PC

BO_ 2333081455 D2M_SUMDATA4__47: 8 DCDC
 SG_ D2M_SUMDATA4_CRC_47 : 0|8@1+ (1,0) [0|255] ""  MBMU,PC
 SG_ D2M_DCDC_FaultCode_47 : 8|8@1+ (1,0) [0|255] ""  MBMU,PC
 SG_ D2M_DCDC_FaultClass_47 : 16|3@1+ (1,0) [0|7] ""  MBMU,PC
 SG_ D2M_DCDC_FaultNum_47 : 19|8@1+ (1,0) [0|255] ""  MBMU,PC
 SG_ D2M_SUMDATA4_Reserved_47 : 27|32@1+ (1,0) [0|4294967295] ""  MBMU,PC

BO_ 2333081456 D2M_SUMDATA4__48: 8 DCDC
 SG_ D2M_SUMDATA4_CRC_48 : 0|8@1+ (1,0) [0|255] ""  MBMU,PC
 SG_ D2M_DCDC_FaultCode_48 : 8|8@1+ (1,0) [0|255] ""  MBMU,PC
 SG_ D2M_DCDC_FaultClass_48 : 16|3@1+ (1,0) [0|7] ""  MBMU,PC
 SG_ D2M_DCDC_FaultNum_48 : 19|8@1+ (1,0) [0|255] ""  MBMU,PC
 SG_ D2M_SUMDATA4_Reserved_48 : 27|32@1+ (1,0) [0|4294967295] ""  MBMU,PC

BO_ 2333081457 D2M_SUMDATA4__49: 8 DCDC
 SG_ D2M_SUMDATA4_CRC_49 : 0|8@1+ (1,0) [0|255] ""  MBMU,PC
 SG_ D2M_DCDC_FaultCode_49 : 8|8@1+ (1,0) [0|255] ""  MBMU,PC
 SG_ D2M_DCDC_FaultClass_49 : 16|3@1+ (1,0) [0|7] ""  MBMU,PC
 SG_ D2M_DCDC_FaultNum_49 : 19|8@1+ (1,0) [0|255] ""  MBMU,PC
 SG_ D2M_SUMDATA4_Reserved_49 : 27|32@1+ (1,0) [0|4294967295] ""  MBMU,PC

BO_ 2333081458 D2M_SUMDATA4__50: 8 DCDC
 SG_ D2M_SUMDATA4_CRC_50 : 0|8@1+ (1,0) [0|255] ""  MBMU,PC
 SG_ D2M_DCDC_FaultCode_50 : 8|8@1+ (1,0) [0|255] ""  MBMU,PC
 SG_ D2M_DCDC_FaultClass_50 : 16|3@1+ (1,0) [0|7] ""  MBMU,PC
 SG_ D2M_DCDC_FaultNum_50 : 19|8@1+ (1,0) [0|255] ""  MBMU,PC
 SG_ D2M_SUMDATA4_Reserved_50 : 27|32@1+ (1,0) [0|4294967295] ""  MBMU,PC

BO_ 2333081459 D2M_SUMDATA4__51: 8 DCDC
 SG_ D2M_SUMDATA4_CRC_51 : 0|8@1+ (1,0) [0|255] ""  MBMU,PC
 SG_ D2M_DCDC_FaultCode_51 : 8|8@1+ (1,0) [0|255] ""  MBMU,PC
 SG_ D2M_DCDC_FaultClass_51 : 16|3@1+ (1,0) [0|7] ""  MBMU,PC
 SG_ D2M_DCDC_FaultNum_51 : 19|8@1+ (1,0) [0|255] ""  MBMU,PC
 SG_ D2M_SUMDATA4_Reserved_51 : 27|32@1+ (1,0) [0|4294967295] ""  MBMU,PC

BO_ 2333081460 D2M_SUMDATA4__52: 8 DCDC
 SG_ D2M_SUMDATA4_CRC_52 : 0|8@1+ (1,0) [0|255] ""  MBMU,PC
 SG_ D2M_DCDC_FaultCode_52 : 8|8@1+ (1,0) [0|255] ""  MBMU,PC
 SG_ D2M_DCDC_FaultClass_52 : 16|3@1+ (1,0) [0|7] ""  MBMU,PC
 SG_ D2M_DCDC_FaultNum_52 : 19|8@1+ (1,0) [0|255] ""  MBMU,PC
 SG_ D2M_SUMDATA4_Reserved_52 : 27|32@1+ (1,0) [0|4294967295] ""  MBMU,PC

BO_ 2333081461 D2M_SUMDATA4__53: 8 DCDC
 SG_ D2M_SUMDATA4_CRC_53 : 0|8@1+ (1,0) [0|255] ""  MBMU,PC
 SG_ D2M_DCDC_FaultCode_53 : 8|8@1+ (1,0) [0|255] ""  MBMU,PC
 SG_ D2M_DCDC_FaultClass_53 : 16|3@1+ (1,0) [0|7] ""  MBMU,PC
 SG_ D2M_DCDC_FaultNum_53 : 19|8@1+ (1,0) [0|255] ""  MBMU,PC
 SG_ D2M_SUMDATA4_Reserved_53 : 27|32@1+ (1,0) [0|4294967295] ""  MBMU,PC

BO_ 2333081462 D2M_SUMDATA4__54: 8 DCDC
 SG_ D2M_SUMDATA4_CRC_54 : 0|8@1+ (1,0) [0|255] ""  MBMU,PC
 SG_ D2M_DCDC_FaultCode_54 : 8|8@1+ (1,0) [0|255] ""  MBMU,PC
 SG_ D2M_DCDC_FaultClass_54 : 16|3@1+ (1,0) [0|7] ""  MBMU,PC
 SG_ D2M_DCDC_FaultNum_54 : 19|8@1+ (1,0) [0|255] ""  MBMU,PC
 SG_ D2M_SUMDATA4_Reserved_54 : 27|32@1+ (1,0) [0|4294967295] ""  MBMU,PC

BO_ 2333081463 D2M_SUMDATA4__55: 8 DCDC
 SG_ D2M_SUMDATA4_CRC_55 : 0|8@1+ (1,0) [0|255] ""  MBMU,PC
 SG_ D2M_DCDC_FaultCode_55 : 8|8@1+ (1,0) [0|255] ""  MBMU,PC
 SG_ D2M_DCDC_FaultClass_55 : 16|3@1+ (1,0) [0|7] ""  MBMU,PC
 SG_ D2M_DCDC_FaultNum_55 : 19|8@1+ (1,0) [0|255] ""  MBMU,PC
 SG_ D2M_SUMDATA4_Reserved_55 : 27|32@1+ (1,0) [0|4294967295] ""  MBMU,PC

BO_ 2333081464 D2M_SUMDATA4__56: 8 DCDC
 SG_ D2M_SUMDATA4_CRC_56 : 0|8@1+ (1,0) [0|255] ""  MBMU,PC
 SG_ D2M_DCDC_FaultCode_56 : 8|8@1+ (1,0) [0|255] ""  MBMU,PC
 SG_ D2M_DCDC_FaultClass_56 : 16|3@1+ (1,0) [0|7] ""  MBMU,PC
 SG_ D2M_DCDC_FaultNum_56 : 19|8@1+ (1,0) [0|255] ""  MBMU,PC
 SG_ D2M_SUMDATA4_Reserved_56 : 27|32@1+ (1,0) [0|4294967295] ""  MBMU,PC

BO_ 2333081465 D2M_SUMDATA4__57: 8 DCDC
 SG_ D2M_SUMDATA4_CRC_57 : 0|8@1+ (1,0) [0|255] ""  MBMU,PC
 SG_ D2M_DCDC_FaultCode_57 : 8|8@1+ (1,0) [0|255] ""  MBMU,PC
 SG_ D2M_DCDC_FaultClass_57 : 16|3@1+ (1,0) [0|7] ""  MBMU,PC
 SG_ D2M_DCDC_FaultNum_57 : 19|8@1+ (1,0) [0|255] ""  MBMU,PC
 SG_ D2M_SUMDATA4_Reserved_57 : 27|32@1+ (1,0) [0|4294967295] ""  MBMU,PC

BO_ 2333081466 D2M_SUMDATA4__58: 8 DCDC
 SG_ D2M_SUMDATA4_CRC_58 : 0|8@1+ (1,0) [0|255] ""  MBMU,PC
 SG_ D2M_DCDC_FaultCode_58 : 8|8@1+ (1,0) [0|255] ""  MBMU,PC
 SG_ D2M_DCDC_FaultClass_58 : 16|3@1+ (1,0) [0|7] ""  MBMU,PC
 SG_ D2M_DCDC_FaultNum_58 : 19|8@1+ (1,0) [0|255] ""  MBMU,PC
 SG_ D2M_SUMDATA4_Reserved_58 : 27|32@1+ (1,0) [0|4294967295] ""  MBMU,PC

BO_ 2333081467 D2M_SUMDATA4__59: 8 DCDC
 SG_ D2M_SUMDATA4_CRC_59 : 0|8@1+ (1,0) [0|255] ""  MBMU,PC
 SG_ D2M_DCDC_FaultCode_59 : 8|8@1+ (1,0) [0|255] ""  MBMU,PC
 SG_ D2M_DCDC_FaultClass_59 : 16|3@1+ (1,0) [0|7] ""  MBMU,PC
 SG_ D2M_DCDC_FaultNum_59 : 19|8@1+ (1,0) [0|255] ""  MBMU,PC
 SG_ D2M_SUMDATA4_Reserved_59 : 27|32@1+ (1,0) [0|4294967295] ""  MBMU,PC

BO_ 2333081468 D2M_SUMDATA4__60: 8 DCDC
 SG_ D2M_SUMDATA4_CRC_60 : 0|8@1+ (1,0) [0|255] ""  MBMU,PC
 SG_ D2M_DCDC_FaultCode_60 : 8|8@1+ (1,0) [0|255] ""  MBMU,PC
 SG_ D2M_DCDC_FaultClass_60 : 16|3@1+ (1,0) [0|7] ""  MBMU,PC
 SG_ D2M_DCDC_FaultNum_60 : 19|8@1+ (1,0) [0|255] ""  MBMU,PC
 SG_ D2M_SUMDATA4_Reserved_60 : 27|32@1+ (1,0) [0|4294967295] ""  MBMU,PC

BO_ 2333081469 D2M_SUMDATA4__61: 8 DCDC
 SG_ D2M_SUMDATA4_CRC_61 : 0|8@1+ (1,0) [0|255] ""  MBMU,PC
 SG_ D2M_DCDC_FaultCode_61 : 8|8@1+ (1,0) [0|255] ""  MBMU,PC
 SG_ D2M_DCDC_FaultClass_61 : 16|3@1+ (1,0) [0|7] ""  MBMU,PC
 SG_ D2M_DCDC_FaultNum_61 : 19|8@1+ (1,0) [0|255] ""  MBMU,PC
 SG_ D2M_SUMDATA4_Reserved_61 : 27|32@1+ (1,0) [0|4294967295] ""  MBMU,PC

BO_ 2333081470 D2M_SUMDATA4__62: 8 DCDC
 SG_ D2M_SUMDATA4_CRC_62 : 0|8@1+ (1,0) [0|255] ""  MBMU,PC
 SG_ D2M_DCDC_FaultCode_62 : 8|8@1+ (1,0) [0|255] ""  MBMU,PC
 SG_ D2M_DCDC_FaultClass_62 : 16|3@1+ (1,0) [0|7] ""  MBMU,PC
 SG_ D2M_DCDC_FaultNum_62 : 19|8@1+ (1,0) [0|255] ""  MBMU,PC
 SG_ D2M_SUMDATA4_Reserved_62 : 27|32@1+ (1,0) [0|4294967295] ""  MBMU,PC

BO_ 2333081471 D2M_SUMDATA4__63: 8 DCDC
 SG_ D2M_SUMDATA4_CRC_63 : 0|8@1+ (1,0) [0|255] ""  MBMU,PC
 SG_ D2M_DCDC_FaultCode_63 : 8|8@1+ (1,0) [0|255] ""  MBMU,PC
 SG_ D2M_DCDC_FaultClass_63 : 16|3@1+ (1,0) [0|7] ""  MBMU,PC
 SG_ D2M_DCDC_FaultNum_63 : 19|8@1+ (1,0) [0|255] ""  MBMU,PC
 SG_ D2M_SUMDATA4_Reserved_63 : 27|32@1+ (1,0) [0|4294967295] ""  MBMU,PC

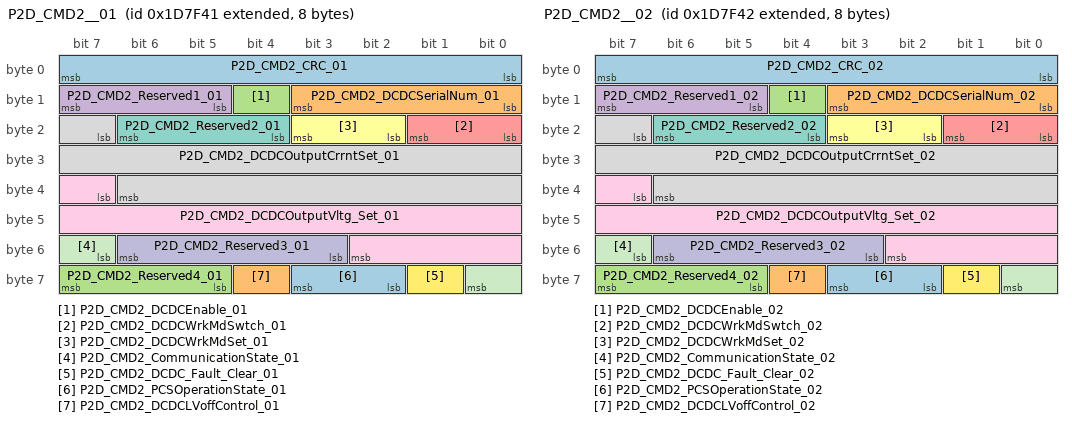
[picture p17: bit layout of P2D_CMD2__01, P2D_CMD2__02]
BO_ 2149416769 P2D_CMD2__01: 8 PC
 SG_ P2D_CMD2_CRC_01 : 0|8@1+ (1,0) [0|255] ""  DCDC
 SG_ P2D_CMD2_DCDCSerialNum_01 : 8|4@1+ (1,0) [0|15] ""  DCDC
 SG_ P2D_CMD2_DCDCEnable_01 : 12|1@1+ (1,0) [0|1] ""  DCDC
 SG_ P2D_CMD2_Reserved1_01 : 13|3@1+ (1,0) [0|7] ""  DCDC
 SG_ P2D_CMD2_DCDCWrkMdSwtch_01 : 16|2@1+ (1,0) [0|3] ""  DCDC
 SG_ P2D_CMD2_DCDCWrkMdSet_01 : 18|2@1+ (1,0) [0|3] ""  DCDC
 SG_ P2D_CMD2_Reserved2_01 : 20|3@1+ (1,0) [0|7] ""  DCDC
 SG_ P2D_CMD2_DCDCOutputCrrntSet_01 : 23|16@1+ (0.05,-2000) [-2000|1276.75] "A"  DCDC
 SG_ P2D_CMD2_DCDCOutputVltg_Set_01 : 39|12@1+ (0.1,-200) [-200|209.5] "V"  DCDC
 SG_ P2D_CMD2_Reserved3_01 : 51|4@1+ (1,0) [0|15] ""  DCDC
 SG_ P2D_CMD2_CommunicationState_01 : 55|2@1+ (1,0) [0|3] ""  DCDC
 SG_ P2D_CMD2_DCDC_Fault_Clear_01 : 57|1@1+ (1,0) [0|1] ""  DCDC
 SG_ P2D_CMD2_PCSOperationState_01 : 58|2@1+ (1,0) [0|3] ""  DCDC
 SG_ P2D_CMD2_DCDCLVoffControl_01 : 60|1@1+ (1,0) [0|1] ""  DCDC
 SG_ P2D_CMD2_Reserved4_01 : 61|3@1+ (1,0) [0|7] ""  DCDC

BO_ 2149416770 P2D_CMD2__02: 8 PC
 SG_ P2D_CMD2_CRC_02 : 0|8@1+ (1,0) [0|255] ""  DCDC
 SG_ P2D_CMD2_DCDCSerialNum_02 : 8|4@1+ (1,0) [0|15] ""  DCDC
 SG_ P2D_CMD2_DCDCEnable_02 : 12|1@1+ (1,0) [0|1] ""  DCDC
 SG_ P2D_CMD2_Reserved1_02 : 13|3@1+ (1,0) [0|7] ""  DCDC
 SG_ P2D_CMD2_DCDCWrkMdSwtch_02 : 16|2@1+ (1,0) [0|3] ""  DCDC
 SG_ P2D_CMD2_DCDCWrkMdSet_02 : 18|2@1+ (1,0) [0|3] ""  DCDC
 SG_ P2D_CMD2_Reserved2_02 : 20|3@1+ (1,0) [0|7] ""  DCDC
 SG_ P2D_CMD2_DCDCOutputCrrntSet_02 : 23|16@1+ (0.05,-2000) [-2000|1276.75] "A"  DCDC
 SG_ P2D_CMD2_DCDCOutputVltg_Set_02 : 39|12@1+ (0.1,-200) [-200|209.5] "V"  DCDC
 SG_ P2D_CMD2_Reserved3_02 : 51|4@1+ (1,0) [0|15] ""  DCDC
 SG_ P2D_CMD2_CommunicationState_02 : 55|2@1+ (1,0) [0|3] ""  DCDC
 SG_ P2D_CMD2_DCDC_Fault_Clear_02 : 57|1@1+ (1,0) [0|1] ""  DCDC
 SG_ P2D_CMD2_PCSOperationState_02 : 58|2@1+ (1,0) [0|3] ""  DCDC
 SG_ P2D_CMD2_DCDCLVoffControl_02 : 60|1@1+ (1,0) [0|1] ""  DCDC
 SG_ P2D_CMD2_Reserved4_02 : 61|3@1+ (1,0) [0|7] ""  DCDC

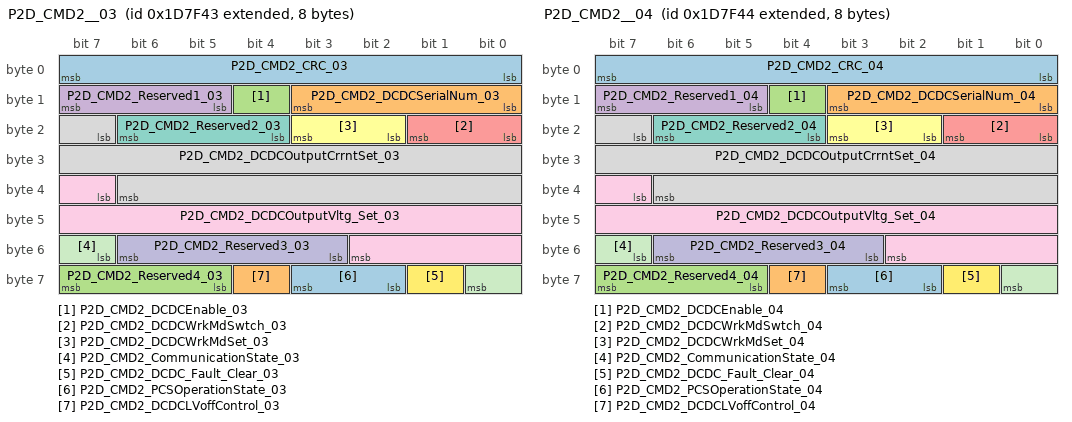
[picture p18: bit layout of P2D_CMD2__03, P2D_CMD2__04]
BO_ 2149416771 P2D_CMD2__03: 8 PC
 SG_ P2D_CMD2_CRC_03 : 0|8@1+ (1,0) [0|255] ""  DCDC
 SG_ P2D_CMD2_DCDCSerialNum_03 : 8|4@1+ (1,0) [0|15] ""  DCDC
 SG_ P2D_CMD2_DCDCEnable_03 : 12|1@1+ (1,0) [0|1] ""  DCDC
 SG_ P2D_CMD2_Reserved1_03 : 13|3@1+ (1,0) [0|7] ""  DCDC
 SG_ P2D_CMD2_DCDCWrkMdSwtch_03 : 16|2@1+ (1,0) [0|3] ""  DCDC
 SG_ P2D_CMD2_DCDCWrkMdSet_03 : 18|2@1+ (1,0) [0|3] ""  DCDC
 SG_ P2D_CMD2_Reserved2_03 : 20|3@1+ (1,0) [0|7] ""  DCDC
 SG_ P2D_CMD2_DCDCOutputCrrntSet_03 : 23|16@1+ (0.05,-2000) [-2000|1276.75] "A"  DCDC
 SG_ P2D_CMD2_DCDCOutputVltg_Set_03 : 39|12@1+ (0.1,-200) [-200|209.5] "V"  DCDC
 SG_ P2D_CMD2_Reserved3_03 : 51|4@1+ (1,0) [0|15] ""  DCDC
 SG_ P2D_CMD2_CommunicationState_03 : 55|2@1+ (1,0) [0|3] ""  DCDC
 SG_ P2D_CMD2_DCDC_Fault_Clear_03 : 57|1@1+ (1,0) [0|1] ""  DCDC
 SG_ P2D_CMD2_PCSOperationState_03 : 58|2@1+ (1,0) [0|3] ""  DCDC
 SG_ P2D_CMD2_DCDCLVoffControl_03 : 60|1@1+ (1,0) [0|1] ""  DCDC
 SG_ P2D_CMD2_Reserved4_03 : 61|3@1+ (1,0) [0|7] ""  DCDC

BO_ 2149416772 P2D_CMD2__04: 8 PC
 SG_ P2D_CMD2_CRC_04 : 0|8@1+ (1,0) [0|255] ""  DCDC
 SG_ P2D_CMD2_DCDCSerialNum_04 : 8|4@1+ (1,0) [0|15] ""  DCDC
 SG_ P2D_CMD2_DCDCEnable_04 : 12|1@1+ (1,0) [0|1] ""  DCDC
 SG_ P2D_CMD2_Reserved1_04 : 13|3@1+ (1,0) [0|7] ""  DCDC
 SG_ P2D_CMD2_DCDCWrkMdSwtch_04 : 16|2@1+ (1,0) [0|3] ""  DCDC
 SG_ P2D_CMD2_DCDCWrkMdSet_04 : 18|2@1+ (1,0) [0|3] ""  DCDC
 SG_ P2D_CMD2_Reserved2_04 : 20|3@1+ (1,0) [0|7] ""  DCDC
 SG_ P2D_CMD2_DCDCOutputCrrntSet_04 : 23|16@1+ (0.05,-2000) [-2000|1276.75] "A"  DCDC
 SG_ P2D_CMD2_DCDCOutputVltg_Set_04 : 39|12@1+ (0.1,-200) [-200|209.5] "V"  DCDC
 SG_ P2D_CMD2_Reserved3_04 : 51|4@1+ (1,0) [0|15] ""  DCDC
 SG_ P2D_CMD2_CommunicationState_04 : 55|2@1+ (1,0) [0|3] ""  DCDC
 SG_ P2D_CMD2_DCDC_Fault_Clear_04 : 57|1@1+ (1,0) [0|1] ""  DCDC
 SG_ P2D_CMD2_PCSOperationState_04 : 58|2@1+ (1,0) [0|3] ""  DCDC
 SG_ P2D_CMD2_DCDCLVoffControl_04 : 60|1@1+ (1,0) [0|1] ""  DCDC
 SG_ P2D_CMD2_Reserved4_04 : 61|3@1+ (1,0) [0|7] ""  DCDC

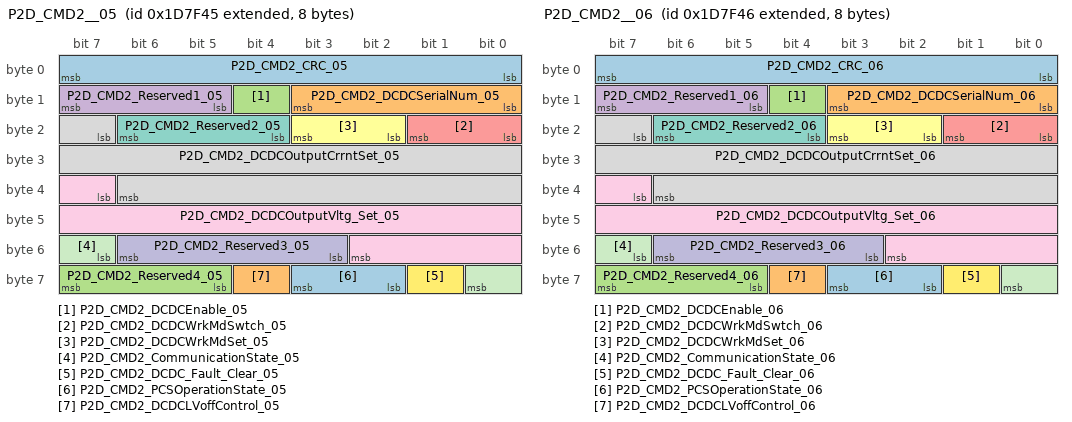
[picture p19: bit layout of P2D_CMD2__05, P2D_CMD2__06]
BO_ 2149416773 P2D_CMD2__05: 8 PC
 SG_ P2D_CMD2_CRC_05 : 0|8@1+ (1,0) [0|255] ""  DCDC
 SG_ P2D_CMD2_DCDCSerialNum_05 : 8|4@1+ (1,0) [0|15] ""  DCDC
 SG_ P2D_CMD2_DCDCEnable_05 : 12|1@1+ (1,0) [0|1] ""  DCDC
 SG_ P2D_CMD2_Reserved1_05 : 13|3@1+ (1,0) [0|7] ""  DCDC
 SG_ P2D_CMD2_DCDCWrkMdSwtch_05 : 16|2@1+ (1,0) [0|3] ""  DCDC
 SG_ P2D_CMD2_DCDCWrkMdSet_05 : 18|2@1+ (1,0) [0|3] ""  DCDC
 SG_ P2D_CMD2_Reserved2_05 : 20|3@1+ (1,0) [0|7] ""  DCDC
 SG_ P2D_CMD2_DCDCOutputCrrntSet_05 : 23|16@1+ (0.05,-2000) [-2000|1276.75] "A"  DCDC
 SG_ P2D_CMD2_DCDCOutputVltg_Set_05 : 39|12@1+ (0.1,-200) [-200|209.5] "V"  DCDC
 SG_ P2D_CMD2_Reserved3_05 : 51|4@1+ (1,0) [0|15] ""  DCDC
 SG_ P2D_CMD2_CommunicationState_05 : 55|2@1+ (1,0) [0|3] ""  DCDC
 SG_ P2D_CMD2_DCDC_Fault_Clear_05 : 57|1@1+ (1,0) [0|1] ""  DCDC
 SG_ P2D_CMD2_PCSOperationState_05 : 58|2@1+ (1,0) [0|3] ""  DCDC
 SG_ P2D_CMD2_DCDCLVoffControl_05 : 60|1@1+ (1,0) [0|1] ""  DCDC
 SG_ P2D_CMD2_Reserved4_05 : 61|3@1+ (1,0) [0|7] ""  DCDC

BO_ 2149416774 P2D_CMD2__06: 8 PC
 SG_ P2D_CMD2_CRC_06 : 0|8@1+ (1,0) [0|255] ""  DCDC
 SG_ P2D_CMD2_DCDCSerialNum_06 : 8|4@1+ (1,0) [0|15] ""  DCDC
 SG_ P2D_CMD2_DCDCEnable_06 : 12|1@1+ (1,0) [0|1] ""  DCDC
 SG_ P2D_CMD2_Reserved1_06 : 13|3@1+ (1,0) [0|7] ""  DCDC
 SG_ P2D_CMD2_DCDCWrkMdSwtch_06 : 16|2@1+ (1,0) [0|3] ""  DCDC
 SG_ P2D_CMD2_DCDCWrkMdSet_06 : 18|2@1+ (1,0) [0|3] ""  DCDC
 SG_ P2D_CMD2_Reserved2_06 : 20|3@1+ (1,0) [0|7] ""  DCDC
 SG_ P2D_CMD2_DCDCOutputCrrntSet_06 : 23|16@1+ (0.05,-2000) [-2000|1276.75] "A"  DCDC
 SG_ P2D_CMD2_DCDCOutputVltg_Set_06 : 39|12@1+ (0.1,-200) [-200|209.5] "V"  DCDC
 SG_ P2D_CMD2_Reserved3_06 : 51|4@1+ (1,0) [0|15] ""  DCDC
 SG_ P2D_CMD2_CommunicationState_06 : 55|2@1+ (1,0) [0|3] ""  DCDC
 SG_ P2D_CMD2_DCDC_Fault_Clear_06 : 57|1@1+ (1,0) [0|1] ""  DCDC
 SG_ P2D_CMD2_PCSOperationState_06 : 58|2@1+ (1,0) [0|3] ""  DCDC
 SG_ P2D_CMD2_DCDCLVoffControl_06 : 60|1@1+ (1,0) [0|1] ""  DCDC
 SG_ P2D_CMD2_Reserved4_06 : 61|3@1+ (1,0) [0|7] ""  DCDC

CM_ SG_ 2332884853 D2M_SUMDATA1_CRC_53 "CRC校验";
CM_ SG_ 2332884853 D2M_SUMDATA1_DCDC_Life_53 "生命信号，0~15循环";
CM_ SG_ 2332884853 D2M_DCDC_RQ_Mode_Set_53 "预留";
CM_ SG_ 2332884853 D2M_DCDC_Work_State_53 "DCDC工作状态";
CM_ SG_ 2332884853 D2M_DCDC_AlarmSigl_State_53 "DCDC Alarm信号状态";
CM_ SG_ 2332884853 D2M_DCDC_LVPower_State_53 "DCDC低压供电电源状态";
CM_ SG_ 2332884853 D2M_DCDC_Enableline_State_53 "DCDC硬线使能信号状态(预留)";
CM_ SG_ 2332884853 D2M_Communication_State_53 "DCDC与MBMU通讯状态";
CM_ SG_ 2332884853 D2M_SUMDATA1_Reserved1_53 "预留1";
CM_ SG_ 2332884853 D2M_DCDC_PCBTemp_53 "DCDC 板温";
CM_ SG_ 2332884853 D2M_DCDC_MosTemp1_53 "DCDC 一级MOS温度";
CM_ SG_ 2332884853 D2M_DCDC_MosTemp2_53 "DCDC 二级MOS温度";
CM_ SG_ 2332884853 D2M_DCDC_TransformerTemp_53 "DCDC 变压器温度";
CM_ SG_ 2332884853 D2M_DCDC_Sleep_State_53 "DCDC休眠状态";
CM_ SG_ 2332884853 D2M_SUMDATA1_Reserved_53 "预留2";
CM_ SG_ 2332884854 D2M_SUMDATA1_CRC_54 "CRC校验";
CM_ SG_ 2332884854 D2M_SUMDATA1_DCDC_Life_54 "生命信号，0~15循环";
CM_ SG_ 2332884854 D2M_DCDC_RQ_Mode_Set_54 "预留";
CM_ SG_ 2332884854 D2M_DCDC_Work_State_54 "DCDC工作状态";
CM_ SG_ 2332884854 D2M_DCDC_AlarmSigl_State_54 "DCDC Alarm信号状态";
CM_ SG_ 2332884854 D2M_DCDC_LVPower_State_54 "DCDC低压供电电源状态";
CM_ SG_ 2332884854 D2M_DCDC_Enableline_State_54 "DCDC硬线使能信号状态(预留)";
CM_ SG_ 2332884854 D2M_Communication_State_54 "DCDC与MBMU通讯状态";
CM_ SG_ 2332884854 D2M_SUMDATA1_Reserved1_54 "预留1";
CM_ SG_ 2332884854 D2M_DCDC_PCBTemp_54 "DCDC 板温";
CM_ SG_ 2332884854 D2M_DCDC_MosTemp1_54 "DCDC 一级MOS温度";
CM_ SG_ 2332884854 D2M_DCDC_MosTemp2_54 "DCDC 二级MOS温度";
CM_ SG_ 2332884854 D2M_DCDC_TransformerTemp_54 "DCDC 变压器温度";
CM_ SG_ 2332884854 D2M_DCDC_Sleep_State_54 "DCDC休眠状态";
CM_ SG_ 2332884854 D2M_SUMDATA1_Reserved_54 "预留2";
CM_ SG_ 2332884855 D2M_SUMDATA1_CRC_55 "CRC校验";
CM_ SG_ 2332884855 D2M_SUMDATA1_DCDC_Life_55 "生命信号，0~15循环";
CM_ SG_ 2332884855 D2M_DCDC_RQ_Mode_Set_55 "预留";
CM_ SG_ 2332884855 D2M_DCDC_Work_State_55 "DCDC工作状态";
CM_ SG_ 2332884855 D2M_DCDC_AlarmSigl_State_55 "DCDC Alarm信号状态";
CM_ SG_ 2332884855 D2M_DCDC_LVPower_State_55 "DCDC低压供电电源状态";
CM_ SG_ 2332884855 D2M_DCDC_Enableline_State_55 "DCDC硬线使能信号状态(预留)";
CM_ SG_ 2332884855 D2M_Communication_State_55 "DCDC与MBMU通讯状态";
CM_ SG_ 2332884855 D2M_SUMDATA1_Reserved1_55 "预留1";
CM_ SG_ 2332884855 D2M_DCDC_PCBTemp_55 "DCDC 板温";
CM_ SG_ 2332884855 D2M_DCDC_MosTemp1_55 "DCDC 一级MOS温度";
CM_ SG_ 2332884855 D2M_DCDC_MosTemp2_55 "DCDC 二级MOS温度";
CM_ SG_ 2332884855 D2M_DCDC_TransformerTemp_55 "DCDC 变压器温度";
CM_ SG_ 2332884855 D2M_DCDC_Sleep_State_55 "DCDC休眠状态";
CM_ SG_ 2332884855 D2M_SUMDATA1_Reserved_55 "预留2";
CM_ SG_ 2332884856 D2M_SUMDATA1_CRC_56 "CRC校验";
CM_ SG_ 2332884856 D2M_SUMDATA1_DCDC_Life_56 "生命信号，0~15循环";
CM_ SG_ 2332884856 D2M_DCDC_RQ_Mode_Set_56 "预留";
CM_ SG_ 2332884856 D2M_DCDC_Work_State_56 "DCDC工作状态";
CM_ SG_ 2332884856 D2M_DCDC_AlarmSigl_State_56 "DCDC Alarm信号状态";
CM_ SG_ 2332884856 D2M_DCDC_LVPower_State_56 "DCDC低压供电电源状态";
CM_ SG_ 2332884856 D2M_DCDC_Enableline_State_56 "DCDC硬线使能信号状态(预留)";
CM_ SG_ 2332884856 D2M_Communication_State_56 "DCDC与MBMU通讯状态";
CM_ SG_ 2332884856 D2M_SUMDATA1_Reserved1_56 "预留1";
CM_ SG_ 2332884856 D2M_DCDC_PCBTemp_56 "DCDC 板温";
CM_ SG_ 2332884856 D2M_DCDC_MosTemp1_56 "DCDC 一级MOS温度";
CM_ SG_ 2332884856 D2M_DCDC_MosTemp2_56 "DCDC 二级MOS温度";
CM_ SG_ 2332884856 D2M_DCDC_TransformerTemp_56 "DCDC 变压器温度";
CM_ SG_ 2332884856 D2M_DCDC_Sleep_State_56 "DCDC休眠状态";
CM_ SG_ 2332884856 D2M_SUMDATA1_Reserved_56 "预留2";
CM_ SG_ 2332884857 D2M_SUMDATA1_CRC_57 "CRC校验";
CM_ SG_ 2332884857 D2M_SUMDATA1_DCDC_Life_57 "生命信号，0~15循环";
CM_ SG_ 2332884857 D2M_DCDC_RQ_Mode_Set_57 "预留";
CM_ SG_ 2332884857 D2M_DCDC_Work_State_57 "DCDC工作状态";
CM_ SG_ 2332884857 D2M_DCDC_AlarmSigl_State_57 "DCDC Alarm信号状态";
CM_ SG_ 2332884857 D2M_DCDC_LVPower_State_57 "DCDC低压供电电源状态";
CM_ SG_ 2332884857 D2M_DCDC_Enableline_State_57 "DCDC硬线使能信号状态(预留)";
CM_ SG_ 2332884857 D2M_Communication_State_57 "DCDC与MBMU通讯状态";
CM_ SG_ 2332884857 D2M_SUMDATA1_Reserved1_57 "预留1";
CM_ SG_ 2332884857 D2M_DCDC_PCBTemp_57 "DCDC 板温";
CM_ SG_ 2332884857 D2M_DCDC_MosTemp1_57 "DCDC 一级MOS温度";
CM_ SG_ 2332884857 D2M_DCDC_MosTemp2_57 "DCDC 二级MOS温度";
CM_ SG_ 2332884857 D2M_DCDC_TransformerTemp_57 "DCDC 变压器温度";
CM_ SG_ 2332884857 D2M_DCDC_Sleep_State_57 "DCDC休眠状态";
CM_ SG_ 2332884857 D2M_SUMDATA1_Reserved_57 "预留2";
CM_ SG_ 2332884858 D2M_SUMDATA1_CRC_58 "CRC校验";
CM_ SG_ 2332884858 D2M_SUMDATA1_DCDC_Life_58 "生命信号，0~15循环";
CM_ SG_ 2332884858 D2M_DCDC_RQ_Mode_Set_58 "预留";
CM_ SG_ 2332884858 D2M_DCDC_Work_State_58 "DCDC工作状态";
CM_ SG_ 2332884858 D2M_DCDC_AlarmSigl_State_58 "DCDC Alarm信号状态";
CM_ SG_ 2332884858 D2M_DCDC_LVPower_State_58 "DCDC低压供电电源状态";
CM_ SG_ 2332884858 D2M_DCDC_Enableline_State_58 "DCDC硬线使能信号状态(预留)";
CM_ SG_ 2332884858 D2M_Communication_State_58 "DCDC与MBMU通讯状态";
CM_ SG_ 2332884858 D2M_SUMDATA1_Reserved1_58 "预留1";
CM_ SG_ 2332884858 D2M_DCDC_PCBTemp_58 "DCDC 板温";
CM_ SG_ 2332884858 D2M_DCDC_MosTemp1_58 "DCDC 一级MOS温度";
CM_ SG_ 2332884858 D2M_DCDC_MosTemp2_58 "DCDC 二级MOS温度";
CM_ SG_ 2332884858 D2M_DCDC_TransformerTemp_58 "DCDC 变压器温度";
CM_ SG_ 2332884858 D2M_DCDC_Sleep_State_58 "DCDC休眠状态";
CM_ SG_ 2332884858 D2M_SUMDATA1_Reserved_58 "预留2";
CM_ SG_ 2332884859 D2M_SUMDATA1_CRC_59 "CRC校验";
CM_ SG_ 2332884859 D2M_SUMDATA1_DCDC_Life_59 "生命信号，0~15循环";
CM_ SG_ 2332884859 D2M_DCDC_RQ_Mode_Set_59 "预留";
CM_ SG_ 2332884859 D2M_DCDC_Work_State_59 "DCDC工作状态";
CM_ SG_ 2332884859 D2M_DCDC_AlarmSigl_State_59 "DCDC Alarm信号状态";
CM_ SG_ 2332884859 D2M_DCDC_LVPower_State_59 "DCDC低压供电电源状态";
CM_ SG_ 2332884859 D2M_DCDC_Enableline_State_59 "DCDC硬线使能信号状态(预留)";
CM_ SG_ 2332884859 D2M_Communication_State_59 "DCDC与MBMU通讯状态";
CM_ SG_ 2332884859 D2M_SUMDATA1_Reserved1_59 "预留1";
CM_ SG_ 2332884859 D2M_DCDC_PCBTemp_59 "DCDC 板温";
CM_ SG_ 2332884859 D2M_DCDC_MosTemp1_59 "DCDC 一级MOS温度";
CM_ SG_ 2332884859 D2M_DCDC_MosTemp2_59 "DCDC 二级MOS温度";
CM_ SG_ 2332884859 D2M_DCDC_TransformerTemp_59 "DCDC 变压器温度";
CM_ SG_ 2332884859 D2M_DCDC_Sleep_State_59 "DCDC休眠状态";
CM_ SG_ 2332884859 D2M_SUMDATA1_Reserved_59 "预留2";
CM_ SG_ 2332884860 D2M_SUMDATA1_CRC_60 "CRC校验";
CM_ SG_ 2332884860 D2M_SUMDATA1_DCDC_Life_60 "生命信号，0~15循环";
CM_ SG_ 2332884860 D2M_DCDC_RQ_Mode_Set_60 "预留";
CM_ SG_ 2332884860 D2M_DCDC_Work_State_60 "DCDC工作状态";
CM_ SG_ 2332884860 D2M_DCDC_AlarmSigl_State_60 "DCDC Alarm信号状态";
CM_ SG_ 2332884860 D2M_DCDC_LVPower_State_60 "DCDC低压供电电源状态";
CM_ SG_ 2332884860 D2M_DCDC_Enableline_State_60 "DCDC硬线使能信号状态(预留)";
CM_ SG_ 2332884860 D2M_Communication_State_60 "DCDC与MBMU通讯状态";
CM_ SG_ 2332884860 D2M_SUMDATA1_Reserved1_60 "预留1";
CM_ SG_ 2332884860 D2M_DCDC_PCBTemp_60 "DCDC 板温";
CM_ SG_ 2332884860 D2M_DCDC_MosTemp1_60 "DCDC 一级MOS温度";
CM_ SG_ 2332884860 D2M_DCDC_MosTemp2_60 "DCDC 二级MOS温度";
CM_ SG_ 2332884860 D2M_DCDC_TransformerTemp_60 "DCDC 变压器温度";
CM_ SG_ 2332884860 D2M_DCDC_Sleep_State_60 "DCDC休眠状态";
CM_ SG_ 2332884860 D2M_SUMDATA1_Reserved_60 "预留2";
CM_ SG_ 2332884861 D2M_SUMDATA1_CRC_61 "CRC校验";
CM_ SG_ 2332884861 D2M_SUMDATA1_DCDC_Life_61 "生命信号，0~15循环";
CM_ SG_ 2332884861 D2M_DCDC_RQ_Mode_Set_61 "预留";
CM_ SG_ 2332884861 D2M_DCDC_Work_State_61 "DCDC工作状态";
CM_ SG_ 2332884861 D2M_DCDC_AlarmSigl_State_61 "DCDC Alarm信号状态";
CM_ SG_ 2332884861 D2M_DCDC_LVPower_State_61 "DCDC低压供电电源状态";
CM_ SG_ 2332884861 D2M_DCDC_Enableline_State_61 "DCDC硬线使能信号状态(预留)";
CM_ SG_ 2332884861 D2M_Communication_State_61 "DCDC与MBMU通讯状态";
CM_ SG_ 2332884861 D2M_SUMDATA1_Reserved1_61 "预留1";
CM_ SG_ 2332884861 D2M_DCDC_PCBTemp_61 "DCDC 板温";
CM_ SG_ 2332884861 D2M_DCDC_MosTemp1_61 "DCDC 一级MOS温度";
CM_ SG_ 2332884861 D2M_DCDC_MosTemp2_61 "DCDC 二级MOS温度";
CM_ SG_ 2332884861 D2M_DCDC_TransformerTemp_61 "DCDC 变压器温度";
CM_ SG_ 2332884861 D2M_DCDC_Sleep_State_61 "DCDC休眠状态";
CM_ SG_ 2332884861 D2M_SUMDATA1_Reserved_61 "预留2";
CM_ SG_ 2332884862 D2M_SUMDATA1_CRC_62 "CRC校验";
CM_ SG_ 2332884862 D2M_SUMDATA1_DCDC_Life_62 "生命信号，0~15循环";
CM_ SG_ 2332884862 D2M_DCDC_RQ_Mode_Set_62 "预留";
CM_ SG_ 2332884862 D2M_DCDC_Work_State_62 "DCDC工作状态";
CM_ SG_ 2332884862 D2M_DCDC_AlarmSigl_State_62 "DCDC Alarm信号状态";
CM_ SG_ 2332884862 D2M_DCDC_LVPower_State_62 "DCDC低压供电电源状态";
CM_ SG_ 2332884862 D2M_DCDC_Enableline_State_62 "DCDC硬线使能信号状态(预留)";
CM_ SG_ 2332884862 D2M_Communication_State_62 "DCDC与MBMU通讯状态";
CM_ SG_ 2332884862 D2M_SUMDATA1_Reserved1_62 "预留1";
CM_ SG_ 2332884862 D2M_DCDC_PCBTemp_62 "DCDC 板温";
CM_ SG_ 2332884862 D2M_DCDC_MosTemp1_62 "DCDC 一级MOS温度";
CM_ SG_ 2332884862 D2M_DCDC_MosTemp2_62 "DCDC 二级MOS温度";
CM_ SG_ 2332884862 D2M_DCDC_TransformerTemp_62 "DCDC 变压器温度";
CM_ SG_ 2332884862 D2M_DCDC_Sleep_State_62 "DCDC休眠状态";
CM_ SG_ 2332884862 D2M_SUMDATA1_Reserved_62 "预留2";
CM_ SG_ 2332884863 D2M_SUMDATA1_CRC_63 "CRC校验";
CM_ SG_ 2332884863 D2M_SUMDATA1_DCDC_Life_63 "生命信号，0~15循环";
CM_ SG_ 2332884863 D2M_DCDC_RQ_Mode_Set_63 "预留";
CM_ SG_ 2332884863 D2M_DCDC_Work_State_63 "DCDC工作状态";
CM_ SG_ 2332884863 D2M_DCDC_AlarmSigl_State_63 "DCDC Alarm信号状态";
CM_ SG_ 2332884863 D2M_DCDC_LVPower_State_63 "DCDC低压供电电源状态";
CM_ SG_ 2332884863 D2M_DCDC_Enableline_State_63 "DCDC硬线使能信号状态(预留)";
CM_ SG_ 2332884863 D2M_Communication_State_63 "DCDC与MBMU通讯状态";
CM_ SG_ 2332884863 D2M_SUMDATA1_Reserved1_63 "预留1";
CM_ SG_ 2332884863 D2M_DCDC_PCBTemp_63 "DCDC 板温";
CM_ SG_ 2332884863 D2M_DCDC_MosTemp1_63 "DCDC 一级MOS温度";
CM_ SG_ 2332884863 D2M_DCDC_MosTemp2_63 "DCDC 二级MOS温度";
CM_ SG_ 2332884863 D2M_DCDC_TransformerTemp_63 "DCDC 变压器温度";
CM_ SG_ 2332884863 D2M_DCDC_Sleep_State_63 "DCDC休眠状态";
CM_ SG_ 2332884863 D2M_SUMDATA1_Reserved_63 "预留2";
CM_ SG_ 2332950337 D2M_SUMDATA2_CRC_01 "CRC校验";
CM_ SG_ 2332950337 D2M_DCDC_Output_Voltage_01 "DCDC输出电压";
CM_ SG_ 2332950337 D2M_DCDC_Input_Voltage_01 "DCDC输入电压";
CM_ SG_ 2332950337 D2M_DCDC_Output_Current_01 "DCDC输出电流（放正充负；旁路时此电流=电池电流=支路电流；功率输出时，此电流=支路电流=电池电流-低压端电流）";
CM_ SG_ 2332950337 D2M_DCDC_Input_Current_01 "DCDC输入电流";
CM_ SG_ 2332950338 D2M_SUMDATA2_CRC_02 "CRC校验";
CM_ SG_ 2332950338 D2M_DCDC_Output_Voltage_02 "DCDC输出电压";
CM_ SG_ 2332950338 D2M_DCDC_Input_Voltage_02 "DCDC输入电压";
CM_ SG_ 2332950338 D2M_DCDC_Output_Current_02 "DCDC输出电流（放正充负；旁路时此电流=电池电流=支路电流；功率输出时，此电流=支路电流=电池电流-低压端电流）";
CM_ SG_ 2332950338 D2M_DCDC_Input_Current_02 "DCDC输入电流";
CM_ SG_ 2332950339 D2M_SUMDATA2_CRC_03 "CRC校验";
CM_ SG_ 2332950339 D2M_DCDC_Output_Voltage_03 "DCDC输出电压";
CM_ SG_ 2332950339 D2M_DCDC_Input_Voltage_03 "DCDC输入电压";
CM_ SG_ 2332950339 D2M_DCDC_Output_Current_03 "DCDC输出电流（放正充负；旁路时此电流=电池电流=支路电流；功率输出时，此电流=支路电流=电池电流-低压端电流）";
CM_ SG_ 2332950339 D2M_DCDC_Input_Current_03 "DCDC输入电流";
CM_ SG_ 2332950340 D2M_SUMDATA2_CRC_04 "CRC校验";
CM_ SG_ 2332950340 D2M_DCDC_Output_Voltage_04 "DCDC输出电压";
CM_ SG_ 2332950340 D2M_DCDC_Input_Voltage_04 "DCDC输入电压";
CM_ SG_ 2332950340 D2M_DCDC_Output_Current_04 "DCDC输出电流（放正充负；旁路时此电流=电池电流=支路电流；功率输出时，此电流=支路电流=电池电流-低压端电流）";
CM_ SG_ 2332950340 D2M_DCDC_Input_Current_04 "DCDC输入电流";
CM_ SG_ 2332950341 D2M_SUMDATA2_CRC_05 "CRC校验";
CM_ SG_ 2332950341 D2M_DCDC_Output_Voltage_05 "DCDC输出电压";
CM_ SG_ 2332950341 D2M_DCDC_Input_Voltage_05 "DCDC输入电压";
CM_ SG_ 2332950341 D2M_DCDC_Output_Current_05 "DCDC输出电流（放正充负；旁路时此电流=电池电流=支路电流；功率输出时，此电流=支路电流=电池电流-低压端电流）";
CM_ SG_ 2332950341 D2M_DCDC_Input_Current_05 "DCDC输入电流";
CM_ SG_ 2332950342 D2M_SUMDATA2_CRC_06 "CRC校验";
CM_ SG_ 2332950342 D2M_DCDC_Output_Voltage_06 "DCDC输出电压";
CM_ SG_ 2332950342 D2M_DCDC_Input_Voltage_06 "DCDC输入电压";
CM_ SG_ 2332950342 D2M_DCDC_Output_Current_06 "DCDC输出电流（放正充负；旁路时此电流=电池电流=支路电流；功率输出时，此电流=支路电流=电池电流-低压端电流）";
CM_ SG_ 2332950342 D2M_DCDC_Input_Current_06 "DCDC输入电流";
CM_ SG_ 2332950343 D2M_SUMDATA2_CRC_07 "CRC校验";
CM_ SG_ 2332950343 D2M_DCDC_Output_Voltage_07 "DCDC输出电压";
CM_ SG_ 2332950343 D2M_DCDC_Input_Voltage_07 "DCDC输入电压";
CM_ SG_ 2332950343 D2M_DCDC_Output_Current_07 "DCDC输出电流（放正充负；旁路时此电流=电池电流=支路电流；功率输出时，此电流=支路电流=电池电流-低压端电流）";
CM_ SG_ 2332950343 D2M_DCDC_Input_Current_07 "DCDC输入电流";
CM_ SG_ 2332950344 D2M_SUMDATA2_CRC_08 "CRC校验";
CM_ SG_ 2332950344 D2M_DCDC_Output_Voltage_08 "DCDC输出电压";
CM_ SG_ 2332950344 D2M_DCDC_Input_Voltage_08 "DCDC输入电压";
CM_ SG_ 2332950344 D2M_DCDC_Output_Current_08 "DCDC输出电流（放正充负；旁路时此电流=电池电流=支路电流；功率输出时，此电流=支路电流=电池电流-低压端电流）";
CM_ SG_ 2332950344 D2M_DCDC_Input_Current_08 "DCDC输入电流";
CM_ SG_ 2332950345 D2M_SUMDATA2_CRC_09 "CRC校验";
CM_ SG_ 2332950345 D2M_DCDC_Output_Voltage_09 "DCDC输出电压";
CM_ SG_ 2332950345 D2M_DCDC_Input_Voltage_09 "DCDC输入电压";
CM_ SG_ 2332950345 D2M_DCDC_Output_Current_09 "DCDC输出电流（放正充负；旁路时此电流=电池电流=支路电流；功率输出时，此电流=支路电流=电池电流-低压端电流）";
CM_ SG_ 2332950345 D2M_DCDC_Input_Current_09 "DCDC输入电流";
CM_ SG_ 2332950346 D2M_SUMDATA2_CRC_10 "CRC校验";
CM_ SG_ 2332950346 D2M_DCDC_Output_Voltage_10 "DCDC输出电压";
CM_ SG_ 2332950346 D2M_DCDC_Input_Voltage_10 "DCDC输入电压";
CM_ SG_ 2332950346 D2M_DCDC_Output_Current_10 "DCDC输出电流（放正充负；旁路时此电流=电池电流=支路电流；功率输出时，此电流=支路电流=电池电流-低压端电流）";
CM_ SG_ 2332950346 D2M_DCDC_Input_Current_10 "DCDC输入电流";
CM_ SG_ 2332950347 D2M_SUMDATA2_CRC_11 "CRC校验";
CM_ SG_ 2332950347 D2M_DCDC_Output_Voltage_11 "DCDC输出电压";
CM_ SG_ 2332950347 D2M_DCDC_Input_Voltage_11 "DCDC输入电压";
CM_ SG_ 2332950347 D2M_DCDC_Output_Current_11 "DCDC输出电流（放正充负；旁路时此电流=电池电流=支路电流；功率输出时，此电流=支路电流=电池电流-低压端电流）";
CM_ SG_ 2332950347 D2M_DCDC_Input_Current_11 "DCDC输入电流";
CM_ SG_ 2332950348 D2M_SUMDATA2_CRC_12 "CRC校验";
CM_ SG_ 2332950348 D2M_DCDC_Output_Voltage_12 "DCDC输出电压";
CM_ SG_ 2332950348 D2M_DCDC_Input_Voltage_12 "DCDC输入电压";
CM_ SG_ 2332950348 D2M_DCDC_Output_Current_12 "DCDC输出电流（放正充负；旁路时此电流=电池电流=支路电流；功率输出时，此电流=支路电流=电池电流-低压端电流）";
CM_ SG_ 2332950348 D2M_DCDC_Input_Current_12 "DCDC输入电流";
CM_ SG_ 2332950349 D2M_SUMDATA2_CRC_13 "CRC校验";
CM_ SG_ 2332950349 D2M_DCDC_Output_Voltage_13 "DCDC输出电压";
CM_ SG_ 2332950349 D2M_DCDC_Input_Voltage_13 "DCDC输入电压";
CM_ SG_ 2332950349 D2M_DCDC_Output_Current_13 "DCDC输出电流（放正充负；旁路时此电流=电池电流=支路电流；功率输出时，此电流=支路电流=电池电流-低压端电流）";
CM_ SG_ 2332950349 D2M_DCDC_Input_Current_13 "DCDC输入电流";
CM_ SG_ 2332950350 D2M_SUMDATA2_CRC_14 "CRC校验";
CM_ SG_ 2332950350 D2M_DCDC_Output_Voltage_14 "DCDC输出电压";
CM_ SG_ 2332950350 D2M_DCDC_Input_Voltage_14 "DCDC输入电压";
CM_ SG_ 2332950350 D2M_DCDC_Output_Current_14 "DCDC输出电流（放正充负；旁路时此电流=电池电流=支路电流；功率输出时，此电流=支路电流=电池电流-低压端电流）";
CM_ SG_ 2332950350 D2M_DCDC_Input_Current_14 "DCDC输入电流";
CM_ SG_ 2332950351 D2M_SUMDATA2_CRC_15 "CRC校验";
CM_ SG_ 2332950351 D2M_DCDC_Output_Voltage_15 "DCDC输出电压";
CM_ SG_ 2332950351 D2M_DCDC_Input_Voltage_15 "DCDC输入电压";
CM_ SG_ 2332950351 D2M_DCDC_Output_Current_15 "DCDC输出电流（放正充负；旁路时此电流=电池电流=支路电流；功率输出时，此电流=支路电流=电池电流-低压端电流）";
CM_ SG_ 2332950351 D2M_DCDC_Input_Current_15 "DCDC输入电流";
CM_ SG_ 2332950352 D2M_SUMDATA2_CRC_16 "CRC校验";
CM_ SG_ 2332950352 D2M_DCDC_Output_Voltage_16 "DCDC输出电压";
CM_ SG_ 2332950352 D2M_DCDC_Input_Voltage_16 "DCDC输入电压";
CM_ SG_ 2332950352 D2M_DCDC_Output_Current_16 "DCDC输出电流（放正充负；旁路时此电流=电池电流=支路电流；功率输出时，此电流=支路电流=电池电流-低压端电流）";
CM_ SG_ 2332950352 D2M_DCDC_Input_Current_16 "DCDC输入电流";
CM_ SG_ 2332950353 D2M_SUMDATA2_CRC_17 "CRC校验";
CM_ SG_ 2332950353 D2M_DCDC_Output_Voltage_17 "DCDC输出电压";
CM_ SG_ 2332950353 D2M_DCDC_Input_Voltage_17 "DCDC输入电压";
CM_ SG_ 2332950353 D2M_DCDC_Output_Current_17 "DCDC输出电流（放正充负；旁路时此电流=电池电流=支路电流；功率输出时，此电流=支路电流=电池电流-低压端电流）";
CM_ SG_ 2332950353 D2M_DCDC_Input_Current_17 "DCDC输入电流";
CM_ SG_ 2332950354 D2M_SUMDATA2_CRC_18 "CRC校验";
CM_ SG_ 2332950354 D2M_DCDC_Output_Voltage_18 "DCDC输出电压";
CM_ SG_ 2332950354 D2M_DCDC_Input_Voltage_18 "DCDC输入电压";
CM_ SG_ 2332950354 D2M_DCDC_Output_Current_18 "DCDC输出电流（放正充负；旁路时此电流=电池电流=支路电流；功率输出时，此电流=支路电流=电池电流-低压端电流）";
CM_ SG_ 2332950354 D2M_DCDC_Input_Current_18 "DCDC输入电流";
CM_ SG_ 2332950355 D2M_SUMDATA2_CRC_19 "CRC校验";
CM_ SG_ 2332950355 D2M_DCDC_Output_Voltage_19 "DCDC输出电压";
CM_ SG_ 2332950355 D2M_DCDC_Input_Voltage_19 "DCDC输入电压";
CM_ SG_ 2332950355 D2M_DCDC_Output_Current_19 "DCDC输出电流（放正充负；旁路时此电流=电池电流=支路电流；功率输出时，此电流=支路电流=电池电流-低压端电流）";
CM_ SG_ 2332950355 D2M_DCDC_Input_Current_19 "DCDC输入电流";
CM_ SG_ 2332950356 D2M_SUMDATA2_CRC_20 "CRC校验";
CM_ SG_ 2332950356 D2M_DCDC_Output_Voltage_20 "DCDC输出电压";
CM_ SG_ 2332950356 D2M_DCDC_Input_Voltage_20 "DCDC输入电压";
CM_ SG_ 2332950356 D2M_DCDC_Output_Current_20 "DCDC输出电流（放正充负；旁路时此电流=电池电流=支路电流；功率输出时，此电流=支路电流=电池电流-低压端电流）";
CM_ SG_ 2332950356 D2M_DCDC_Input_Current_20 "DCDC输入电流";
CM_ SG_ 2332950357 D2M_SUMDATA2_CRC_21 "CRC校验";
CM_ SG_ 2332950357 D2M_DCDC_Output_Voltage_21 "DCDC输出电压";
CM_ SG_ 2332950357 D2M_DCDC_Input_Voltage_21 "DCDC输入电压";
CM_ SG_ 2332950357 D2M_DCDC_Output_Current_21 "DCDC输出电流（放正充负；旁路时此电流=电池电流=支路电流；功率输出时，此电流=支路电流=电池电流-低压端电流）";
CM_ SG_ 2332950357 D2M_DCDC_Input_Current_21 "DCDC输入电流";
CM_ SG_ 2332950358 D2M_SUMDATA2_CRC_22 "CRC校验";
CM_ SG_ 2332950358 D2M_DCDC_Output_Voltage_22 "DCDC输出电压";
CM_ SG_ 2332950358 D2M_DCDC_Input_Voltage_22 "DCDC输入电压";
CM_ SG_ 2332950358 D2M_DCDC_Output_Current_22 "DCDC输出电流（放正充负；旁路时此电流=电池电流=支路电流；功率输出时，此电流=支路电流=电池电流-低压端电流）";
CM_ SG_ 2332950358 D2M_DCDC_Input_Current_22 "DCDC输入电流";
CM_ SG_ 2332950359 D2M_SUMDATA2_CRC_23 "CRC校验";
CM_ SG_ 2332950359 D2M_DCDC_Output_Voltage_23 "DCDC输出电压";
CM_ SG_ 2332950359 D2M_DCDC_Input_Voltage_23 "DCDC输入电压";
CM_ SG_ 2332950359 D2M_DCDC_Output_Current_23 "DCDC输出电流（放正充负；旁路时此电流=电池电流=支路电流；功率输出时，此电流=支路电流=电池电流-低压端电流）";
CM_ SG_ 2332950359 D2M_DCDC_Input_Current_23 "DCDC输入电流";
CM_ SG_ 2332950360 D2M_SUMDATA2_CRC_24 "CRC校验";
CM_ SG_ 2332950360 D2M_DCDC_Output_Voltage_24 "DCDC输出电压";
CM_ SG_ 2332950360 D2M_DCDC_Input_Voltage_24 "DCDC输入电压";
CM_ SG_ 2332950360 D2M_DCDC_Output_Current_24 "DCDC输出电流（放正充负；旁路时此电流=电池电流=支路电流；功率输出时，此电流=支路电流=电池电流-低压端电流）";
CM_ SG_ 2332950360 D2M_DCDC_Input_Current_24 "DCDC输入电流";
CM_ SG_ 2332950361 D2M_SUMDATA2_CRC_25 "CRC校验";
CM_ SG_ 2332950361 D2M_DCDC_Output_Voltage_25 "DCDC输出电压";
CM_ SG_ 2332950361 D2M_DCDC_Input_Voltage_25 "DCDC输入电压";
CM_ SG_ 2332950361 D2M_DCDC_Output_Current_25 "DCDC输出电流（放正充负；旁路时此电流=电池电流=支路电流；功率输出时，此电流=支路电流=电池电流-低压端电流）";
CM_ SG_ 2332950361 D2M_DCDC_Input_Current_25 "DCDC输入电流";
CM_ SG_ 2332950362 D2M_SUMDATA2_CRC_26 "CRC校验";
CM_ SG_ 2332950362 D2M_DCDC_Output_Voltage_26 "DCDC输出电压";
CM_ SG_ 2332950362 D2M_DCDC_Input_Voltage_26 "DCDC输入电压";
CM_ SG_ 2332950362 D2M_DCDC_Output_Current_26 "DCDC输出电流（放正充负；旁路时此电流=电池电流=支路电流；功率输出时，此电流=支路电流=电池电流-低压端电流）";
CM_ SG_ 2332950362 D2M_DCDC_Input_Current_26 "DCDC输入电流";
CM_ SG_ 2332950363 D2M_SUMDATA2_CRC_27 "CRC校验";
CM_ SG_ 2332950363 D2M_DCDC_Output_Voltage_27 "DCDC输出电压";
CM_ SG_ 2332950363 D2M_DCDC_Input_Voltage_27 "DCDC输入电压";
CM_ SG_ 2332950363 D2M_DCDC_Output_Current_27 "DCDC输出电流（放正充负；旁路时此电流=电池电流=支路电流；功率输出时，此电流=支路电流=电池电流-低压端电流）";
CM_ SG_ 2332950363 D2M_DCDC_Input_Current_27 "DCDC输入电流";
CM_ SG_ 2332950364 D2M_SUMDATA2_CRC_28 "CRC校验";
CM_ SG_ 2332950364 D2M_DCDC_Output_Voltage_28 "DCDC输出电压";
CM_ SG_ 2332950364 D2M_DCDC_Input_Voltage_28 "DCDC输入电压";
CM_ SG_ 2332950364 D2M_DCDC_Output_Current_28 "DCDC输出电流（放正充负；旁路时此电流=电池电流=支路电流；功率输出时，此电流=支路电流=电池电流-低压端电流）";
CM_ SG_ 2332950364 D2M_DCDC_Input_Current_28 "DCDC输入电流";
CM_ SG_ 2332950365 D2M_SUMDATA2_CRC_29 "CRC校验";
CM_ SG_ 2332950365 D2M_DCDC_Output_Voltage_29 "DCDC输出电压";
CM_ SG_ 2332950365 D2M_DCDC_Input_Voltage_29 "DCDC输入电压";
CM_ SG_ 2332950365 D2M_DCDC_Output_Current_29 "DCDC输出电流（放正充负；旁路时此电流=电池电流=支路电流；功率输出时，此电流=支路电流=电池电流-低压端电流）";
CM_ SG_ 2332950365 D2M_DCDC_Input_Current_29 "DCDC输入电流";
CM_ SG_ 2332950366 D2M_SUMDATA2_CRC_30 "CRC校验";
CM_ SG_ 2332950366 D2M_DCDC_Output_Voltage_30 "DCDC输出电压";
CM_ SG_ 2332950366 D2M_DCDC_Input_Voltage_30 "DCDC输入电压";
CM_ SG_ 2332950366 D2M_DCDC_Output_Current_30 "DCDC输出电流（放正充负；旁路时此电流=电池电流=支路电流；功率输出时，此电流=支路电流=电池电流-低压端电流）";
CM_ SG_ 2332950366 D2M_DCDC_Input_Current_30 "DCDC输入电流";
CM_ SG_ 2332950367 D2M_SUMDATA2_CRC_31 "CRC校验";
CM_ SG_ 2332950367 D2M_DCDC_Output_Voltage_31 "DCDC输出电压";
CM_ SG_ 2332950367 D2M_DCDC_Input_Voltage_31 "DCDC输入电压";
CM_ SG_ 2332950367 D2M_DCDC_Output_Current_31 "DCDC输出电流（放正充负；旁路时此电流=电池电流=支路电流；功率输出时，此电流=支路电流=电池电流-低压端电流）";
CM_ SG_ 2332950367 D2M_DCDC_Input_Current_31 "DCDC输入电流";
CM_ SG_ 2332950368 D2M_SUMDATA2_CRC_32 "CRC校验";
CM_ SG_ 2332950368 D2M_DCDC_Output_Voltage_32 "DCDC输出电压";
CM_ SG_ 2332950368 D2M_DCDC_Input_Voltage_32 "DCDC输入电压";
CM_ SG_ 2332950368 D2M_DCDC_Output_Current_32 "DCDC输出电流（放正充负；旁路时此电流=电池电流=支路电流；功率输出时，此电流=支路电流=电池电流-低压端电流）";
CM_ SG_ 2332950368 D2M_DCDC_Input_Current_32 "DCDC输入电流";
CM_ SG_ 2332950369 D2M_SUMDATA2_CRC_33 "CRC校验";
CM_ SG_ 2332950369 D2M_DCDC_Output_Voltage_33 "DCDC输出电压";
CM_ SG_ 2332950369 D2M_DCDC_Input_Voltage_33 "DCDC输入电压";
CM_ SG_ 2332950369 D2M_DCDC_Output_Current_33 "DCDC输出电流（放正充负；旁路时此电流=电池电流=支路电流；功率输出时，此电流=支路电流=电池电流-低压端电流）";
CM_ SG_ 2332950369 D2M_DCDC_Input_Current_33 "DCDC输入电流";
CM_ SG_ 2332950370 D2M_SUMDATA2_CRC_34 "CRC校验";
CM_ SG_ 2332950370 D2M_DCDC_Output_Voltage_34 "DCDC输出电压";
CM_ SG_ 2332950370 D2M_DCDC_Input_Voltage_34 "DCDC输入电压";
CM_ SG_ 2332950370 D2M_DCDC_Output_Current_34 "DCDC输出电流（放正充负；旁路时此电流=电池电流=支路电流；功率输出时，此电流=支路电流=电池电流-低压端电流）";
CM_ SG_ 2332950370 D2M_DCDC_Input_Current_34 "DCDC输入电流";
CM_ SG_ 2332950371 D2M_SUMDATA2_CRC_35 "CRC校验";
CM_ SG_ 2332950371 D2M_DCDC_Output_Voltage_35 "DCDC输出电压";
CM_ SG_ 2332950371 D2M_DCDC_Input_Voltage_35 "DCDC输入电压";
CM_ SG_ 2332950371 D2M_DCDC_Output_Current_35 "DCDC输出电流（放正充负；旁路时此电流=电池电流=支路电流；功率输出时，此电流=支路电流=电池电流-低压端电流）";
CM_ SG_ 2332950371 D2M_DCDC_Input_Current_35 "DCDC输入电流";
CM_ SG_ 2332950372 D2M_SUMDATA2_CRC_36 "CRC校验";
CM_ SG_ 2332950372 D2M_DCDC_Output_Voltage_36 "DCDC输出电压";
CM_ SG_ 2332950372 D2M_DCDC_Input_Voltage_36 "DCDC输入电压";
CM_ SG_ 2332950372 D2M_DCDC_Output_Current_36 "DCDC输出电流（放正充负；旁路时此电流=电池电流=支路电流；功率输出时，此电流=支路电流=电池电流-低压端电流）";
CM_ SG_ 2332950372 D2M_DCDC_Input_Current_36 "DCDC输入电流";
CM_ SG_ 2332950373 D2M_SUMDATA2_CRC_37 "CRC校验";
CM_ SG_ 2332950373 D2M_DCDC_Output_Voltage_37 "DCDC输出电压";
CM_ SG_ 2332950373 D2M_DCDC_Input_Voltage_37 "DCDC输入电压";
CM_ SG_ 2332950373 D2M_DCDC_Output_Current_37 "DCDC输出电流（放正充负；旁路时此电流=电池电流=支路电流；功率输出时，此电流=支路电流=电池电流-低压端电流）";
CM_ SG_ 2332950373 D2M_DCDC_Input_Current_37 "DCDC输入电流";
CM_ SG_ 2332950374 D2M_SUMDATA2_CRC_38 "CRC校验";
CM_ SG_ 2332950374 D2M_DCDC_Output_Voltage_38 "DCDC输出电压";
CM_ SG_ 2332950374 D2M_DCDC_Input_Voltage_38 "DCDC输入电压";
CM_ SG_ 2332950374 D2M_DCDC_Output_Current_38 "DCDC输出电流（放正充负；旁路时此电流=电池电流=支路电流；功率输出时，此电流=支路电流=电池电流-低压端电流）";
CM_ SG_ 2332950374 D2M_DCDC_Input_Current_38 "DCDC输入电流";
CM_ SG_ 2332950375 D2M_SUMDATA2_CRC_39 "CRC校验";
CM_ SG_ 2332950375 D2M_DCDC_Output_Voltage_39 "DCDC输出电压";
CM_ SG_ 2332950375 D2M_DCDC_Input_Voltage_39 "DCDC输入电压";
CM_ SG_ 2332950375 D2M_DCDC_Output_Current_39 "DCDC输出电流（放正充负；旁路时此电流=电池电流=支路电流；功率输出时，此电流=支路电流=电池电流-低压端电流）";
CM_ SG_ 2332950375 D2M_DCDC_Input_Current_39 "DCDC输入电流";
CM_ SG_ 2332950376 D2M_SUMDATA2_CRC_40 "CRC校验";
CM_ SG_ 2332950376 D2M_DCDC_Output_Voltage_40 "DCDC输出电压";
CM_ SG_ 2332950376 D2M_DCDC_Input_Voltage_40 "DCDC输入电压";
CM_ SG_ 2332950376 D2M_DCDC_Output_Current_40 "DCDC输出电流（放正充负；旁路时此电流=电池电流=支路电流；功率输出时，此电流=支路电流=电池电流-低压端电流）";
CM_ SG_ 2332950376 D2M_DCDC_Input_Current_40 "DCDC输入电流";
CM_ SG_ 2332950377 D2M_SUMDATA2_CRC_41 "CRC校验";
CM_ SG_ 2332950377 D2M_DCDC_Output_Voltage_41 "DCDC输出电压";
CM_ SG_ 2332950377 D2M_DCDC_Input_Voltage_41 "DCDC输入电压";
CM_ SG_ 2332950377 D2M_DCDC_Output_Current_41 "DCDC输出电流（放正充负；旁路时此电流=电池电流=支路电流；功率输出时，此电流=支路电流=电池电流-低压端电流）";
CM_ SG_ 2332950377 D2M_DCDC_Input_Current_41 "DCDC输入电流";
CM_ SG_ 2332950378 D2M_SUMDATA2_CRC_42 "CRC校验";
CM_ SG_ 2332950378 D2M_DCDC_Output_Voltage_42 "DCDC输出电压";
CM_ SG_ 2332950378 D2M_DCDC_Input_Voltage_42 "DCDC输入电压";
CM_ SG_ 2332950378 D2M_DCDC_Output_Current_42 "DCDC输出电流（放正充负；旁路时此电流=电池电流=支路电流；功率输出时，此电流=支路电流=电池电流-低压端电流）";
CM_ SG_ 2332950378 D2M_DCDC_Input_Current_42 "DCDC输入电流";
CM_ SG_ 2332950379 D2M_SUMDATA2_CRC_43 "CRC校验";
CM_ SG_ 2332950379 D2M_DCDC_Output_Voltage_43 "DCDC输出电压";
CM_ SG_ 2332950379 D2M_DCDC_Input_Voltage_43 "DCDC输入电压";
CM_ SG_ 2332950379 D2M_DCDC_Output_Current_43 "DCDC输出电流（放正充负；旁路时此电流=电池电流=支路电流；功率输出时，此电流=支路电流=电池电流-低压端电流）";
CM_ SG_ 2332950379 D2M_DCDC_Input_Current_43 "DCDC输入电流";
CM_ SG_ 2332950380 D2M_SUMDATA2_CRC_44 "CRC校验";
CM_ SG_ 2332950380 D2M_DCDC_Output_Voltage_44 "DCDC输出电压";
CM_ SG_ 2332950380 D2M_DCDC_Input_Voltage_44 "DCDC输入电压";
CM_ SG_ 2332950380 D2M_DCDC_Output_Current_44 "DCDC输出电流（放正充负；旁路时此电流=电池电流=支路电流；功率输出时，此电流=支路电流=电池电流-低压端电流）";
CM_ SG_ 2332950380 D2M_DCDC_Input_Current_44 "DCDC输入电流";
CM_ SG_ 2332950381 D2M_SUMDATA2_CRC_45 "CRC校验";
CM_ SG_ 2332950381 D2M_DCDC_Output_Voltage_45 "DCDC输出电压";
CM_ SG_ 2332950381 D2M_DCDC_Input_Voltage_45 "DCDC输入电压";
CM_ SG_ 2332950381 D2M_DCDC_Output_Current_45 "DCDC输出电流（放正充负；旁路时此电流=电池电流=支路电流；功率输出时，此电流=支路电流=电池电流-低压端电流）";
CM_ SG_ 2332950381 D2M_DCDC_Input_Current_45 "DCDC输入电流";
CM_ SG_ 2332950382 D2M_SUMDATA2_CRC_46 "CRC校验";
CM_ SG_ 2332950382 D2M_DCDC_Output_Voltage_46 "DCDC输出电压";
CM_ SG_ 2332950382 D2M_DCDC_Input_Voltage_46 "DCDC输入电压";
CM_ SG_ 2332950382 D2M_DCDC_Output_Current_46 "DCDC输出电流（放正充负；旁路时此电流=电池电流=支路电流；功率输出时，此电流=支路电流=电池电流-低压端电流）";
CM_ SG_ 2332950382 D2M_DCDC_Input_Current_46 "DCDC输入电流";
CM_ SG_ 2332950383 D2M_SUMDATA2_CRC_47 "CRC校验";
CM_ SG_ 2332950383 D2M_DCDC_Output_Voltage_47 "DCDC输出电压";
CM_ SG_ 2332950383 D2M_DCDC_Input_Voltage_47 "DCDC输入电压";
CM_ SG_ 2332950383 D2M_DCDC_Output_Current_47 "DCDC输出电流（放正充负；旁路时此电流=电池电流=支路电流；功率输出时，此电流=支路电流=电池电流-低压端电流）";
CM_ SG_ 2332950383 D2M_DCDC_Input_Current_47 "DCDC输入电流";
CM_ SG_ 2332950384 D2M_SUMDATA2_CRC_48 "CRC校验";
CM_ SG_ 2332950384 D2M_DCDC_Output_Voltage_48 "DCDC输出电压";
CM_ SG_ 2332950384 D2M_DCDC_Input_Voltage_48 "DCDC输入电压";
CM_ SG_ 2332950384 D2M_DCDC_Output_Current_48 "DCDC输出电流（放正充负；旁路时此电流=电池电流=支路电流；功率输出时，此电流=支路电流=电池电流-低压端电流）";
CM_ SG_ 2332950384 D2M_DCDC_Input_Current_48 "DCDC输入电流";
CM_ SG_ 2332950385 D2M_SUMDATA2_CRC_49 "CRC校验";
CM_ SG_ 2332950385 D2M_DCDC_Output_Voltage_49 "DCDC输出电压";
CM_ SG_ 2332950385 D2M_DCDC_Input_Voltage_49 "DCDC输入电压";
CM_ SG_ 2332950385 D2M_DCDC_Output_Current_49 "DCDC输出电流（放正充负；旁路时此电流=电池电流=支路电流；功率输出时，此电流=支路电流=电池电流-低压端电流）";
CM_ SG_ 2332950385 D2M_DCDC_Input_Current_49 "DCDC输入电流";
CM_ SG_ 2332950386 D2M_SUMDATA2_CRC_50 "CRC校验";
CM_ SG_ 2332950386 D2M_DCDC_Output_Voltage_50 "DCDC输出电压";
CM_ SG_ 2332950386 D2M_DCDC_Input_Voltage_50 "DCDC输入电压";
CM_ SG_ 2332950386 D2M_DCDC_Output_Current_50 "DCDC输出电流（放正充负；旁路时此电流=电池电流=支路电流；功率输出时，此电流=支路电流=电池电流-低压端电流）";
CM_ SG_ 2332950386 D2M_DCDC_Input_Current_50 "DCDC输入电流";
CM_ SG_ 2332950387 D2M_SUMDATA2_CRC_51 "CRC校验";
CM_ SG_ 2332950387 D2M_DCDC_Output_Voltage_51 "DCDC输出电压";
CM_ SG_ 2332950387 D2M_DCDC_Input_Voltage_51 "DCDC输入电压";
CM_ SG_ 2332950387 D2M_DCDC_Output_Current_51 "DCDC输出电流（放正充负；旁路时此电流=电池电流=支路电流；功率输出时，此电流=支路电流=电池电流-低压端电流）";
CM_ SG_ 2332950387 D2M_DCDC_Input_Current_51 "DCDC输入电流";
CM_ SG_ 2332950388 D2M_SUMDATA2_CRC_52 "CRC校验";
CM_ SG_ 2332950388 D2M_DCDC_Output_Voltage_52 "DCDC输出电压";
CM_ SG_ 2332950388 D2M_DCDC_Input_Voltage_52 "DCDC输入电压";
CM_ SG_ 2332950388 D2M_DCDC_Output_Current_52 "DCDC输出电流（放正充负；旁路时此电流=电池电流=支路电流；功率输出时，此电流=支路电流=电池电流-低压端电流）";
CM_ SG_ 2332950388 D2M_DCDC_Input_Current_52 "DCDC输入电流";
CM_ SG_ 2332950389 D2M_SUMDATA2_CRC_53 "CRC校验";
CM_ SG_ 2332950389 D2M_DCDC_Output_Voltage_53 "DCDC输出电压";
CM_ SG_ 2332950389 D2M_DCDC_Input_Voltage_53 "DCDC输入电压";
CM_ SG_ 2332950389 D2M_DCDC_Output_Current_53 "DCDC输出电流（放正充负；旁路时此电流=电池电流=支路电流；功率输出时，此电流=支路电流=电池电流-低压端电流）";
CM_ SG_ 2332950389 D2M_DCDC_Input_Current_53 "DCDC输入电流";
CM_ SG_ 2332950390 D2M_SUMDATA2_CRC_54 "CRC校验";
CM_ SG_ 2332950390 D2M_DCDC_Output_Voltage_54 "DCDC输出电压";
CM_ SG_ 2332950390 D2M_DCDC_Input_Voltage_54 "DCDC输入电压";
CM_ SG_ 2332950390 D2M_DCDC_Output_Current_54 "DCDC输出电流（放正充负；旁路时此电流=电池电流=支路电流；功率输出时，此电流=支路电流=电池电流-低压端电流）";
CM_ SG_ 2332950390 D2M_DCDC_Input_Current_54 "DCDC输入电流";
CM_ SG_ 2332950391 D2M_SUMDATA2_CRC_55 "CRC校验";
CM_ SG_ 2332950391 D2M_DCDC_Output_Voltage_55 "DCDC输出电压";
CM_ SG_ 2332950391 D2M_DCDC_Input_Voltage_55 "DCDC输入电压";
CM_ SG_ 2332950391 D2M_DCDC_Output_Current_55 "DCDC输出电流（放正充负；旁路时此电流=电池电流=支路电流；功率输出时，此电流=支路电流=电池电流-低压端电流）";
CM_ SG_ 2332950391 D2M_DCDC_Input_Current_55 "DCDC输入电流";
CM_ SG_ 2332950392 D2M_SUMDATA2_CRC_56 "CRC校验";
CM_ SG_ 2332950392 D2M_DCDC_Output_Voltage_56 "DCDC输出电压";
CM_ SG_ 2332950392 D2M_DCDC_Input_Voltage_56 "DCDC输入电压";
CM_ SG_ 2332950392 D2M_DCDC_Output_Current_56 "DCDC输出电流（放正充负；旁路时此电流=电池电流=支路电流；功率输出时，此电流=支路电流=电池电流-低压端电流）";
CM_ SG_ 2332950392 D2M_DCDC_Input_Current_56 "DCDC输入电流";
CM_ SG_ 2332950393 D2M_SUMDATA2_CRC_57 "CRC校验";
CM_ SG_ 2332950393 D2M_DCDC_Output_Voltage_57 "DCDC输出电压";
CM_ SG_ 2332950393 D2M_DCDC_Input_Voltage_57 "DCDC输入电压";
CM_ SG_ 2332950393 D2M_DCDC_Output_Current_57 "DCDC输出电流（放正充负；旁路时此电流=电池电流=支路电流；功率输出时，此电流=支路电流=电池电流-低压端电流）";
CM_ SG_ 2332950393 D2M_DCDC_Input_Current_57 "DCDC输入电流";
CM_ SG_ 2332950394 D2M_SUMDATA2_CRC_58 "CRC校验";
CM_ SG_ 2332950394 D2M_DCDC_Output_Voltage_58 "DCDC输出电压";
CM_ SG_ 2332950394 D2M_DCDC_Input_Voltage_58 "DCDC输入电压";
CM_ SG_ 2332950394 D2M_DCDC_Output_Current_58 "DCDC输出电流（放正充负；旁路时此电流=电池电流=支路电流；功率输出时，此电流=支路电流=电池电流-低压端电流）";
CM_ SG_ 2332950394 D2M_DCDC_Input_Current_58 "DCDC输入电流";
CM_ SG_ 2332950395 D2M_SUMDATA2_CRC_59 "CRC校验";
CM_ SG_ 2332950395 D2M_DCDC_Output_Voltage_59 "DCDC输出电压";
CM_ SG_ 2332950395 D2M_DCDC_Input_Voltage_59 "DCDC输入电压";
CM_ SG_ 2332950395 D2M_DCDC_Output_Current_59 "DCDC输出电流（放正充负；旁路时此电流=电池电流=支路电流；功率输出时，此电流=支路电流=电池电流-低压端电流）";
CM_ SG_ 2332950395 D2M_DCDC_Input_Current_59 "DCDC输入电流";
CM_ SG_ 2332950396 D2M_SUMDATA2_CRC_60 "CRC校验";
CM_ SG_ 2332950396 D2M_DCDC_Output_Voltage_60 "DCDC输出电压";
CM_ SG_ 2332950396 D2M_DCDC_Input_Voltage_60 "DCDC输入电压";
CM_ SG_ 2332950396 D2M_DCDC_Output_Current_60 "DCDC输出电流（放正充负；旁路时此电流=电池电流=支路电流；功率输出时，此电流=支路电流=电池电流-低压端电流）";
CM_ SG_ 2332950396 D2M_DCDC_Input_Current_60 "DCDC输入电流";
CM_ SG_ 2332950397 D2M_SUMDATA2_CRC_61 "CRC校验";
CM_ SG_ 2332950397 D2M_DCDC_Output_Voltage_61 "DCDC输出电压";
CM_ SG_ 2332950397 D2M_DCDC_Input_Voltage_61 "DCDC输入电压";
CM_ SG_ 2332950397 D2M_DCDC_Output_Current_61 "DCDC输出电流（放正充负；旁路时此电流=电池电流=支路电流；功率输出时，此电流=支路电流=电池电流-低压端电流）";
CM_ SG_ 2332950397 D2M_DCDC_Input_Current_61 "DCDC输入电流";
CM_ SG_ 2332950398 D2M_SUMDATA2_CRC_62 "CRC校验";
CM_ SG_ 2332950398 D2M_DCDC_Output_Voltage_62 "DCDC输出电压";
CM_ SG_ 2332950398 D2M_DCDC_Input_Voltage_62 "DCDC输入电压";
CM_ SG_ 2332950398 D2M_DCDC_Output_Current_62 "DCDC输出电流（放正充负；旁路时此电流=电池电流=支路电流；功率输出时，此电流=支路电流=电池电流-低压端电流）";
CM_ SG_ 2332950398 D2M_DCDC_Input_Current_62 "DCDC输入电流";
CM_ SG_ 2332950399 D2M_SUMDATA2_CRC_63 "CRC校验";
CM_ SG_ 2332950399 D2M_DCDC_Output_Voltage_63 "DCDC输出电压";
CM_ SG_ 2332950399 D2M_DCDC_Input_Voltage_63 "DCDC输入电压";
CM_ SG_ 2332950399 D2M_DCDC_Output_Current_63 "DCDC输出电流（放正充负；旁路时此电流=电池电流=支路电流；功率输出时，此电流=支路电流=电池电流-低压端电流）";
CM_ SG_ 2332950399 D2M_DCDC_Input_Current_63 "DCDC输入电流";
CM_ SG_ 2333015873 D2M_SUMDATA3_CRC_01 "CRC校验";
CM_ SG_ 2333015873 D2M_DCDCLVPowerCurrent_01 "DCDC低压电源电流";
CM_ SG_ 2333015873 D2M_DCDCLVPowerVoltage_01 "DCDC低压电源电压";
CM_ SG_ 2333015873 D2M_DCDCDischrgCrrntLimt_01 "DCDC当前允许最大放电电流限制";
CM_ SG_ 2333015873 D2M_DCDCChrgeCrrnt_Limt_01 "DCDC当前允许最大充电电流限制";
CM_ SG_ 2333015873 D2M_SUMDATA3_Reserved_01 "预留";
CM_ SG_ 2333015874 D2M_SUMDATA3_CRC_02 "CRC校验";
CM_ SG_ 2333015874 D2M_DCDCLVPowerCurrent_02 "DCDC低压电源电流";
CM_ SG_ 2333015874 D2M_DCDCLVPowerVoltage_02 "DCDC低压电源电压";
CM_ SG_ 2333015874 D2M_DCDCDischrgCrrntLimt_02 "DCDC当前允许最大放电电流限制";
CM_ SG_ 2333015874 D2M_DCDCChrgeCrrnt_Limt_02 "DCDC当前允许最大充电电流限制";
CM_ SG_ 2333015874 D2M_SUMDATA3_Reserved_02 "预留";
CM_ SG_ 2333015875 D2M_SUMDATA3_CRC_03 "CRC校验";
CM_ SG_ 2333015875 D2M_DCDCLVPowerCurrent_03 "DCDC低压电源电流";
CM_ SG_ 2333015875 D2M_DCDCLVPowerVoltage_03 "DCDC低压电源电压";
CM_ SG_ 2333015875 D2M_DCDCDischrgCrrntLimt_03 "DCDC当前允许最大放电电流限制";
CM_ SG_ 2333015875 D2M_DCDCChrgeCrrnt_Limt_03 "DCDC当前允许最大充电电流限制";
CM_ SG_ 2333015875 D2M_SUMDATA3_Reserved_03 "预留";
CM_ SG_ 2333015876 D2M_SUMDATA3_CRC_04 "CRC校验";
CM_ SG_ 2333015876 D2M_DCDCLVPowerCurrent_04 "DCDC低压电源电流";
CM_ SG_ 2333015876 D2M_DCDCLVPowerVoltage_04 "DCDC低压电源电压";
CM_ SG_ 2333015876 D2M_DCDCDischrgCrrntLimt_04 "DCDC当前允许最大放电电流限制";
CM_ SG_ 2333015876 D2M_DCDCChrgeCrrnt_Limt_04 "DCDC当前允许最大充电电流限制";
CM_ SG_ 2333015876 D2M_SUMDATA3_Reserved_04 "预留";
CM_ SG_ 2333015877 D2M_SUMDATA3_CRC_05 "CRC校验";
CM_ SG_ 2333015877 D2M_DCDCLVPowerCurrent_05 "DCDC低压电源电流";
CM_ SG_ 2333015877 D2M_DCDCLVPowerVoltage_05 "DCDC低压电源电压";
CM_ SG_ 2333015877 D2M_DCDCDischrgCrrntLimt_05 "DCDC当前允许最大放电电流限制";
CM_ SG_ 2333015877 D2M_DCDCChrgeCrrnt_Limt_05 "DCDC当前允许最大充电电流限制";
CM_ SG_ 2333015877 D2M_SUMDATA3_Reserved_05 "预留";
CM_ SG_ 2333015878 D2M_SUMDATA3_CRC_06 "CRC校验";
CM_ SG_ 2333015878 D2M_DCDCLVPowerCurrent_06 "DCDC低压电源电流";
CM_ SG_ 2333015878 D2M_DCDCLVPowerVoltage_06 "DCDC低压电源电压";
CM_ SG_ 2333015878 D2M_DCDCDischrgCrrntLimt_06 "DCDC当前允许最大放电电流限制";
CM_ SG_ 2333015878 D2M_DCDCChrgeCrrnt_Limt_06 "DCDC当前允许最大充电电流限制";
CM_ SG_ 2333015878 D2M_SUMDATA3_Reserved_06 "预留";
CM_ SG_ 2333015879 D2M_SUMDATA3_CRC_07 "CRC校验";
CM_ SG_ 2333015879 D2M_DCDCLVPowerCurrent_07 "DCDC低压电源电流";
CM_ SG_ 2333015879 D2M_DCDCLVPowerVoltage_07 "DCDC低压电源电压";
CM_ SG_ 2333015879 D2M_DCDCDischrgCrrntLimt_07 "DCDC当前允许最大放电电流限制";
CM_ SG_ 2333015879 D2M_DCDCChrgeCrrnt_Limt_07 "DCDC当前允许最大充电电流限制";
CM_ SG_ 2333015879 D2M_SUMDATA3_Reserved_07 "预留";
CM_ SG_ 2333015880 D2M_SUMDATA3_CRC_08 "CRC校验";
CM_ SG_ 2333015880 D2M_DCDCLVPowerCurrent_08 "DCDC低压电源电流";
CM_ SG_ 2333015880 D2M_DCDCLVPowerVoltage_08 "DCDC低压电源电压";
CM_ SG_ 2333015880 D2M_DCDCDischrgCrrntLimt_08 "DCDC当前允许最大放电电流限制";
CM_ SG_ 2333015880 D2M_DCDCChrgeCrrnt_Limt_08 "DCDC当前允许最大充电电流限制";
CM_ SG_ 2333015880 D2M_SUMDATA3_Reserved_08 "预留";
CM_ SG_ 2333015881 D2M_SUMDATA3_CRC_09 "CRC校验";
CM_ SG_ 2333015881 D2M_DCDCLVPowerCurrent_09 "DCDC低压电源电流";
CM_ SG_ 2333015881 D2M_DCDCLVPowerVoltage_09 "DCDC低压电源电压";
CM_ SG_ 2333015881 D2M_DCDCDischrgCrrntLimt_09 "DCDC当前允许最大放电电流限制";
CM_ SG_ 2333015881 D2M_DCDCChrgeCrrnt_Limt_09 "DCDC当前允许最大充电电流限制";
CM_ SG_ 2333015881 D2M_SUMDATA3_Reserved_09 "预留";
CM_ SG_ 2333015882 D2M_SUMDATA3_CRC_10 "CRC校验";
CM_ SG_ 2333015882 D2M_DCDCLVPowerCurrent_10 "DCDC低压电源电流";
CM_ SG_ 2333015882 D2M_DCDCLVPowerVoltage_10 "DCDC低压电源电压";
CM_ SG_ 2333015882 D2M_DCDCDischrgCrrntLimt_10 "DCDC当前允许最大放电电流限制";
CM_ SG_ 2333015882 D2M_DCDCChrgeCrrnt_Limt_10 "DCDC当前允许最大充电电流限制";
CM_ SG_ 2333015882 D2M_SUMDATA3_Reserved_10 "预留";
CM_ SG_ 2333015883 D2M_SUMDATA3_CRC_11 "CRC校验";
CM_ SG_ 2333015883 D2M_DCDCLVPowerCurrent_11 "DCDC低压电源电流";
CM_ SG_ 2333015883 D2M_DCDCLVPowerVoltage_11 "DCDC低压电源电压";
CM_ SG_ 2333015883 D2M_DCDCDischrgCrrntLimt_11 "DCDC当前允许最大放电电流限制";
CM_ SG_ 2333015883 D2M_DCDCChrgeCrrnt_Limt_11 "DCDC当前允许最大充电电流限制";
CM_ SG_ 2333015883 D2M_SUMDATA3_Reserved_11 "预留";
CM_ SG_ 2333015884 D2M_SUMDATA3_CRC_12 "CRC校验";
CM_ SG_ 2333015884 D2M_DCDCLVPowerCurrent_12 "DCDC低压电源电流";
CM_ SG_ 2333015884 D2M_DCDCLVPowerVoltage_12 "DCDC低压电源电压";
CM_ SG_ 2333015884 D2M_DCDCDischrgCrrntLimt_12 "DCDC当前允许最大放电电流限制";
CM_ SG_ 2333015884 D2M_DCDCChrgeCrrnt_Limt_12 "DCDC当前允许最大充电电流限制";
CM_ SG_ 2333015884 D2M_SUMDATA3_Reserved_12 "预留";
CM_ SG_ 2333015885 D2M_SUMDATA3_CRC_13 "CRC校验";
CM_ SG_ 2333015885 D2M_DCDCLVPowerCurrent_13 "DCDC低压电源电流";
CM_ SG_ 2333015885 D2M_DCDCLVPowerVoltage_13 "DCDC低压电源电压";
CM_ SG_ 2333015885 D2M_DCDCDischrgCrrntLimt_13 "DCDC当前允许最大放电电流限制";
CM_ SG_ 2333015885 D2M_DCDCChrgeCrrnt_Limt_13 "DCDC当前允许最大充电电流限制";
CM_ SG_ 2333015885 D2M_SUMDATA3_Reserved_13 "预留";
CM_ SG_ 2333015886 D2M_SUMDATA3_CRC_14 "CRC校验";
CM_ SG_ 2333015886 D2M_DCDCLVPowerCurrent_14 "DCDC低压电源电流";
CM_ SG_ 2333015886 D2M_DCDCLVPowerVoltage_14 "DCDC低压电源电压";
CM_ SG_ 2333015886 D2M_DCDCDischrgCrrntLimt_14 "DCDC当前允许最大放电电流限制";
CM_ SG_ 2333015886 D2M_DCDCChrgeCrrnt_Limt_14 "DCDC当前允许最大充电电流限制";
CM_ SG_ 2333015886 D2M_SUMDATA3_Reserved_14 "预留";
CM_ SG_ 2333015887 D2M_SUMDATA3_CRC_15 "CRC校验";
CM_ SG_ 2333015887 D2M_DCDCLVPowerCurrent_15 "DCDC低压电源电流";
CM_ SG_ 2333015887 D2M_DCDCLVPowerVoltage_15 "DCDC低压电源电压";
CM_ SG_ 2333015887 D2M_DCDCDischrgCrrntLimt_15 "DCDC当前允许最大放电电流限制";
CM_ SG_ 2333015887 D2M_DCDCChrgeCrrnt_Limt_15 "DCDC当前允许最大充电电流限制";
CM_ SG_ 2333015887 D2M_SUMDATA3_Reserved_15 "预留";
CM_ SG_ 2333015888 D2M_SUMDATA3_CRC_16 "CRC校验";
CM_ SG_ 2333015888 D2M_DCDCLVPowerCurrent_16 "DCDC低压电源电流";
CM_ SG_ 2333015888 D2M_DCDCLVPowerVoltage_16 "DCDC低压电源电压";
CM_ SG_ 2333015888 D2M_DCDCDischrgCrrntLimt_16 "DCDC当前允许最大放电电流限制";
CM_ SG_ 2333015888 D2M_DCDCChrgeCrrnt_Limt_16 "DCDC当前允许最大充电电流限制";
CM_ SG_ 2333015888 D2M_SUMDATA3_Reserved_16 "预留";
CM_ SG_ 2333015889 D2M_SUMDATA3_CRC_17 "CRC校验";
CM_ SG_ 2333015889 D2M_DCDCLVPowerCurrent_17 "DCDC低压电源电流";
CM_ SG_ 2333015889 D2M_DCDCLVPowerVoltage_17 "DCDC低压电源电压";
CM_ SG_ 2333015889 D2M_DCDCDischrgCrrntLimt_17 "DCDC当前允许最大放电电流限制";
CM_ SG_ 2333015889 D2M_DCDCChrgeCrrnt_Limt_17 "DCDC当前允许最大充电电流限制";
CM_ SG_ 2333015889 D2M_SUMDATA3_Reserved_17 "预留";
CM_ SG_ 2333015890 D2M_SUMDATA3_CRC_18 "CRC校验";
CM_ SG_ 2333015890 D2M_DCDCLVPowerCurrent_18 "DCDC低压电源电流";
CM_ SG_ 2333015890 D2M_DCDCLVPowerVoltage_18 "DCDC低压电源电压";
CM_ SG_ 2333015890 D2M_DCDCDischrgCrrntLimt_18 "DCDC当前允许最大放电电流限制";
CM_ SG_ 2333015890 D2M_DCDCChrgeCrrnt_Limt_18 "DCDC当前允许最大充电电流限制";
CM_ SG_ 2333015890 D2M_SUMDATA3_Reserved_18 "预留";
CM_ SG_ 2333015891 D2M_SUMDATA3_CRC_19 "CRC校验";
CM_ SG_ 2333015891 D2M_DCDCLVPowerCurrent_19 "DCDC低压电源电流";
CM_ SG_ 2333015891 D2M_DCDCLVPowerVoltage_19 "DCDC低压电源电压";
CM_ SG_ 2333015891 D2M_DCDCDischrgCrrntLimt_19 "DCDC当前允许最大放电电流限制";
CM_ SG_ 2333015891 D2M_DCDCChrgeCrrnt_Limt_19 "DCDC当前允许最大充电电流限制";
CM_ SG_ 2333015891 D2M_SUMDATA3_Reserved_19 "预留";
CM_ SG_ 2333015892 D2M_SUMDATA3_CRC_20 "CRC校验";
CM_ SG_ 2333015892 D2M_DCDCLVPowerCurrent_20 "DCDC低压电源电流";
CM_ SG_ 2333015892 D2M_DCDCLVPowerVoltage_20 "DCDC低压电源电压";
CM_ SG_ 2333015892 D2M_DCDCDischrgCrrntLimt_20 "DCDC当前允许最大放电电流限制";
CM_ SG_ 2333015892 D2M_DCDCChrgeCrrnt_Limt_20 "DCDC当前允许最大充电电流限制";
CM_ SG_ 2333015892 D2M_SUMDATA3_Reserved_20 "预留";
CM_ SG_ 2333015893 D2M_SUMDATA3_CRC_21 "CRC校验";
CM_ SG_ 2333015893 D2M_DCDCLVPowerCurrent_21 "DCDC低压电源电流";
CM_ SG_ 2333015893 D2M_DCDCLVPowerVoltage_21 "DCDC低压电源电压";
CM_ SG_ 2333015893 D2M_DCDCDischrgCrrntLimt_21 "DCDC当前允许最大放电电流限制";
CM_ SG_ 2333015893 D2M_DCDCChrgeCrrnt_Limt_21 "DCDC当前允许最大充电电流限制";
CM_ SG_ 2333015893 D2M_SUMDATA3_Reserved_21 "预留";
CM_ SG_ 2333015894 D2M_SUMDATA3_CRC_22 "CRC校验";
CM_ SG_ 2333015894 D2M_DCDCLVPowerCurrent_22 "DCDC低压电源电流";
CM_ SG_ 2333015894 D2M_DCDCLVPowerVoltage_22 "DCDC低压电源电压";
CM_ SG_ 2333015894 D2M_DCDCDischrgCrrntLimt_22 "DCDC当前允许最大放电电流限制";
CM_ SG_ 2333015894 D2M_DCDCChrgeCrrnt_Limt_22 "DCDC当前允许最大充电电流限制";
CM_ SG_ 2333015894 D2M_SUMDATA3_Reserved_22 "预留";
CM_ SG_ 2333015895 D2M_SUMDATA3_CRC_23 "CRC校验";
CM_ SG_ 2333015895 D2M_DCDCLVPowerCurrent_23 "DCDC低压电源电流";
CM_ SG_ 2333015895 D2M_DCDCLVPowerVoltage_23 "DCDC低压电源电压";
CM_ SG_ 2333015895 D2M_DCDCDischrgCrrntLimt_23 "DCDC当前允许最大放电电流限制";
CM_ SG_ 2333015895 D2M_DCDCChrgeCrrnt_Limt_23 "DCDC当前允许最大充电电流限制";
CM_ SG_ 2333015895 D2M_SUMDATA3_Reserved_23 "预留";
CM_ SG_ 2333015896 D2M_SUMDATA3_CRC_24 "CRC校验";
CM_ SG_ 2333015896 D2M_DCDCLVPowerCurrent_24 "DCDC低压电源电流";
CM_ SG_ 2333015896 D2M_DCDCLVPowerVoltage_24 "DCDC低压电源电压";
CM_ SG_ 2333015896 D2M_DCDCDischrgCrrntLimt_24 "DCDC当前允许最大放电电流限制";
CM_ SG_ 2333015896 D2M_DCDCChrgeCrrnt_Limt_24 "DCDC当前允许最大充电电流限制";
CM_ SG_ 2333015896 D2M_SUMDATA3_Reserved_24 "预留";
CM_ SG_ 2333015897 D2M_SUMDATA3_CRC_25 "CRC校验";
CM_ SG_ 2333015897 D2M_DCDCLVPowerCurrent_25 "DCDC低压电源电流";
CM_ SG_ 2333015897 D2M_DCDCLVPowerVoltage_25 "DCDC低压电源电压";
CM_ SG_ 2333015897 D2M_DCDCDischrgCrrntLimt_25 "DCDC当前允许最大放电电流限制";
CM_ SG_ 2333015897 D2M_DCDCChrgeCrrnt_Limt_25 "DCDC当前允许最大充电电流限制";
CM_ SG_ 2333015897 D2M_SUMDATA3_Reserved_25 "预留";
CM_ SG_ 2333015898 D2M_SUMDATA3_CRC_26 "CRC校验";
CM_ SG_ 2333015898 D2M_DCDCLVPowerCurrent_26 "DCDC低压电源电流";
CM_ SG_ 2333015898 D2M_DCDCLVPowerVoltage_26 "DCDC低压电源电压";
CM_ SG_ 2333015898 D2M_DCDCDischrgCrrntLimt_26 "DCDC当前允许最大放电电流限制";
CM_ SG_ 2333015898 D2M_DCDCChrgeCrrnt_Limt_26 "DCDC当前允许最大充电电流限制";
CM_ SG_ 2333015898 D2M_SUMDATA3_Reserved_26 "预留";
CM_ SG_ 2333015899 D2M_SUMDATA3_CRC_27 "CRC校验";
CM_ SG_ 2333015899 D2M_DCDCLVPowerCurrent_27 "DCDC低压电源电流";
CM_ SG_ 2333015899 D2M_DCDCLVPowerVoltage_27 "DCDC低压电源电压";
CM_ SG_ 2333015899 D2M_DCDCDischrgCrrntLimt_27 "DCDC当前允许最大放电电流限制";
CM_ SG_ 2333015899 D2M_DCDCChrgeCrrnt_Limt_27 "DCDC当前允许最大充电电流限制";
CM_ SG_ 2333015899 D2M_SUMDATA3_Reserved_27 "预留";
CM_ SG_ 2333015900 D2M_SUMDATA3_CRC_28 "CRC校验";
CM_ SG_ 2333015900 D2M_DCDCLVPowerCurrent_28 "DCDC低压电源电流";
CM_ SG_ 2333015900 D2M_DCDCLVPowerVoltage_28 "DCDC低压电源电压";
CM_ SG_ 2333015900 D2M_DCDCDischrgCrrntLimt_28 "DCDC当前允许最大放电电流限制";
CM_ SG_ 2333015900 D2M_DCDCChrgeCrrnt_Limt_28 "DCDC当前允许最大充电电流限制";
CM_ SG_ 2333015900 D2M_SUMDATA3_Reserved_28 "预留";
CM_ SG_ 2333015901 D2M_SUMDATA3_CRC_29 "CRC校验";
CM_ SG_ 2333015901 D2M_DCDCLVPowerCurrent_29 "DCDC低压电源电流";
CM_ SG_ 2333015901 D2M_DCDCLVPowerVoltage_29 "DCDC低压电源电压";
CM_ SG_ 2333015901 D2M_DCDCDischrgCrrntLimt_29 "DCDC当前允许最大放电电流限制";
CM_ SG_ 2333015901 D2M_DCDCChrgeCrrnt_Limt_29 "DCDC当前允许最大充电电流限制";
CM_ SG_ 2333015901 D2M_SUMDATA3_Reserved_29 "预留";
CM_ SG_ 2333015902 D2M_SUMDATA3_CRC_30 "CRC校验";
CM_ SG_ 2333015902 D2M_DCDCLVPowerCurrent_30 "DCDC低压电源电流";
CM_ SG_ 2333015902 D2M_DCDCLVPowerVoltage_30 "DCDC低压电源电压";
CM_ SG_ 2333015902 D2M_DCDCDischrgCrrntLimt_30 "DCDC当前允许最大放电电流限制";
CM_ SG_ 2333015902 D2M_DCDCChrgeCrrnt_Limt_30 "DCDC当前允许最大充电电流限制";
CM_ SG_ 2333015902 D2M_SUMDATA3_Reserved_30 "预留";
CM_ SG_ 2333015903 D2M_SUMDATA3_CRC_31 "CRC校验";
CM_ SG_ 2333015903 D2M_DCDCLVPowerCurrent_31 "DCDC低压电源电流";
CM_ SG_ 2333015903 D2M_DCDCLVPowerVoltage_31 "DCDC低压电源电压";
CM_ SG_ 2333015903 D2M_DCDCDischrgCrrntLimt_31 "DCDC当前允许最大放电电流限制";
CM_ SG_ 2333015903 D2M_DCDCChrgeCrrnt_Limt_31 "DCDC当前允许最大充电电流限制";
CM_ SG_ 2333015903 D2M_SUMDATA3_Reserved_31 "预留";
CM_ SG_ 2333015904 D2M_SUMDATA3_CRC_32 "CRC校验";
CM_ SG_ 2333015904 D2M_DCDCLVPowerCurrent_32 "DCDC低压电源电流";
CM_ SG_ 2333015904 D2M_DCDCLVPowerVoltage_32 "DCDC低压电源电压";
CM_ SG_ 2333015904 D2M_DCDCDischrgCrrntLimt_32 "DCDC当前允许最大放电电流限制";
CM_ SG_ 2333015904 D2M_DCDCChrgeCrrnt_Limt_32 "DCDC当前允许最大充电电流限制";
CM_ SG_ 2333015904 D2M_SUMDATA3_Reserved_32 "预留";
CM_ SG_ 2333015905 D2M_SUMDATA3_CRC_33 "CRC校验";
CM_ SG_ 2333015905 D2M_DCDCLVPowerCurrent_33 "DCDC低压电源电流";
CM_ SG_ 2333015905 D2M_DCDCLVPowerVoltage_33 "DCDC低压电源电压";
CM_ SG_ 2333015905 D2M_DCDCDischrgCrrntLimt_33 "DCDC当前允许最大放电电流限制";
CM_ SG_ 2333015905 D2M_DCDCChrgeCrrnt_Limt_33 "DCDC当前允许最大充电电流限制";
CM_ SG_ 2333015905 D2M_SUMDATA3_Reserved_33 "预留";
CM_ SG_ 2333015906 D2M_SUMDATA3_CRC_34 "CRC校验";
CM_ SG_ 2333015906 D2M_DCDCLVPowerCurrent_34 "DCDC低压电源电流";
CM_ SG_ 2333015906 D2M_DCDCLVPowerVoltage_34 "DCDC低压电源电压";
CM_ SG_ 2333015906 D2M_DCDCDischrgCrrntLimt_34 "DCDC当前允许最大放电电流限制";
CM_ SG_ 2333015906 D2M_DCDCChrgeCrrnt_Limt_34 "DCDC当前允许最大充电电流限制";
CM_ SG_ 2333015906 D2M_SUMDATA3_Reserved_34 "预留";
CM_ SG_ 2333015907 D2M_SUMDATA3_CRC_35 "CRC校验";
CM_ SG_ 2333015907 D2M_DCDCLVPowerCurrent_35 "DCDC低压电源电流";
CM_ SG_ 2333015907 D2M_DCDCLVPowerVoltage_35 "DCDC低压电源电压";
CM_ SG_ 2333015907 D2M_DCDCDischrgCrrntLimt_35 "DCDC当前允许最大放电电流限制";
CM_ SG_ 2333015907 D2M_DCDCChrgeCrrnt_Limt_35 "DCDC当前允许最大充电电流限制";
CM_ SG_ 2333015907 D2M_SUMDATA3_Reserved_35 "预留";
CM_ SG_ 2333015908 D2M_SUMDATA3_CRC_36 "CRC校验";
CM_ SG_ 2333015908 D2M_DCDCLVPowerCurrent_36 "DCDC低压电源电流";
CM_ SG_ 2333015908 D2M_DCDCLVPowerVoltage_36 "DCDC低压电源电压";
CM_ SG_ 2333015908 D2M_DCDCDischrgCrrntLimt_36 "DCDC当前允许最大放电电流限制";
CM_ SG_ 2333015908 D2M_DCDCChrgeCrrnt_Limt_36 "DCDC当前允许最大充电电流限制";
CM_ SG_ 2333015908 D2M_SUMDATA3_Reserved_36 "预留";
CM_ SG_ 2333015909 D2M_SUMDATA3_CRC_37 "CRC校验";
CM_ SG_ 2333015909 D2M_DCDCLVPowerCurrent_37 "DCDC低压电源电流";
CM_ SG_ 2333015909 D2M_DCDCLVPowerVoltage_37 "DCDC低压电源电压";
CM_ SG_ 2333015909 D2M_DCDCDischrgCrrntLimt_37 "DCDC当前允许最大放电电流限制";
CM_ SG_ 2333015909 D2M_DCDCChrgeCrrnt_Limt_37 "DCDC当前允许最大充电电流限制";
CM_ SG_ 2333015909 D2M_SUMDATA3_Reserved_37 "预留";
CM_ SG_ 2333015910 D2M_SUMDATA3_CRC_38 "CRC校验";
CM_ SG_ 2333015910 D2M_DCDCLVPowerCurrent_38 "DCDC低压电源电流";
CM_ SG_ 2333015910 D2M_DCDCLVPowerVoltage_38 "DCDC低压电源电压";
CM_ SG_ 2333015910 D2M_DCDCDischrgCrrntLimt_38 "DCDC当前允许最大放电电流限制";
CM_ SG_ 2333015910 D2M_DCDCChrgeCrrnt_Limt_38 "DCDC当前允许最大充电电流限制";
CM_ SG_ 2333015910 D2M_SUMDATA3_Reserved_38 "预留";
CM_ SG_ 2333015911 D2M_SUMDATA3_CRC_39 "CRC校验";
CM_ SG_ 2333015911 D2M_DCDCLVPowerCurrent_39 "DCDC低压电源电流";
CM_ SG_ 2333015911 D2M_DCDCLVPowerVoltage_39 "DCDC低压电源电压";
CM_ SG_ 2333015911 D2M_DCDCDischrgCrrntLimt_39 "DCDC当前允许最大放电电流限制";
CM_ SG_ 2333015911 D2M_DCDCChrgeCrrnt_Limt_39 "DCDC当前允许最大充电电流限制";
CM_ SG_ 2333015911 D2M_SUMDATA3_Reserved_39 "预留";
CM_ SG_ 2333015912 D2M_SUMDATA3_CRC_40 "CRC校验";
CM_ SG_ 2333015912 D2M_DCDCLVPowerCurrent_40 "DCDC低压电源电流";
CM_ SG_ 2333015912 D2M_DCDCLVPowerVoltage_40 "DCDC低压电源电压";
CM_ SG_ 2333015912 D2M_DCDCDischrgCrrntLimt_40 "DCDC当前允许最大放电电流限制";
CM_ SG_ 2333015912 D2M_DCDCChrgeCrrnt_Limt_40 "DCDC当前允许最大充电电流限制";
CM_ SG_ 2333015912 D2M_SUMDATA3_Reserved_40 "预留";
CM_ SG_ 2333015913 D2M_SUMDATA3_CRC_41 "CRC校验";
CM_ SG_ 2333015913 D2M_DCDCLVPowerCurrent_41 "DCDC低压电源电流";
CM_ SG_ 2333015913 D2M_DCDCLVPowerVoltage_41 "DCDC低压电源电压";
CM_ SG_ 2333015913 D2M_DCDCDischrgCrrntLimt_41 "DCDC当前允许最大放电电流限制";
CM_ SG_ 2333015913 D2M_DCDCChrgeCrrnt_Limt_41 "DCDC当前允许最大充电电流限制";
CM_ SG_ 2333015913 D2M_SUMDATA3_Reserved_41 "预留";
CM_ SG_ 2333015914 D2M_SUMDATA3_CRC_42 "CRC校验";
CM_ SG_ 2333015914 D2M_DCDCLVPowerCurrent_42 "DCDC低压电源电流";
CM_ SG_ 2333015914 D2M_DCDCLVPowerVoltage_42 "DCDC低压电源电压";
CM_ SG_ 2333015914 D2M_DCDCDischrgCrrntLimt_42 "DCDC当前允许最大放电电流限制";
CM_ SG_ 2333015914 D2M_DCDCChrgeCrrnt_Limt_42 "DCDC当前允许最大充电电流限制";
CM_ SG_ 2333015914 D2M_SUMDATA3_Reserved_42 "预留";
CM_ SG_ 2333015915 D2M_SUMDATA3_CRC_43 "CRC校验";
CM_ SG_ 2333015915 D2M_DCDCLVPowerCurrent_43 "DCDC低压电源电流";
CM_ SG_ 2333015915 D2M_DCDCLVPowerVoltage_43 "DCDC低压电源电压";
CM_ SG_ 2333015915 D2M_DCDCDischrgCrrntLimt_43 "DCDC当前允许最大放电电流限制";
CM_ SG_ 2333015915 D2M_DCDCChrgeCrrnt_Limt_43 "DCDC当前允许最大充电电流限制";
CM_ SG_ 2333015915 D2M_SUMDATA3_Reserved_43 "预留";
CM_ SG_ 2333015916 D2M_SUMDATA3_CRC_44 "CRC校验";
CM_ SG_ 2333015916 D2M_DCDCLVPowerCurrent_44 "DCDC低压电源电流";
CM_ SG_ 2333015916 D2M_DCDCLVPowerVoltage_44 "DCDC低压电源电压";
CM_ SG_ 2333015916 D2M_DCDCDischrgCrrntLimt_44 "DCDC当前允许最大放电电流限制";
CM_ SG_ 2333015916 D2M_DCDCChrgeCrrnt_Limt_44 "DCDC当前允许最大充电电流限制";
CM_ SG_ 2333015916 D2M_SUMDATA3_Reserved_44 "预留";
CM_ SG_ 2333015917 D2M_SUMDATA3_CRC_45 "CRC校验";
CM_ SG_ 2333015917 D2M_DCDCLVPowerCurrent_45 "DCDC低压电源电流";
CM_ SG_ 2333015917 D2M_DCDCLVPowerVoltage_45 "DCDC低压电源电压";
CM_ SG_ 2333015917 D2M_DCDCDischrgCrrntLimt_45 "DCDC当前允许最大放电电流限制";
CM_ SG_ 2333015917 D2M_DCDCChrgeCrrnt_Limt_45 "DCDC当前允许最大充电电流限制";
CM_ SG_ 2333015917 D2M_SUMDATA3_Reserved_45 "预留";
CM_ SG_ 2333015918 D2M_SUMDATA3_CRC_46 "CRC校验";
CM_ SG_ 2333015918 D2M_DCDCLVPowerCurrent_46 "DCDC低压电源电流";
CM_ SG_ 2333015918 D2M_DCDCLVPowerVoltage_46 "DCDC低压电源电压";
CM_ SG_ 2333015918 D2M_DCDCDischrgCrrntLimt_46 "DCDC当前允许最大放电电流限制";
CM_ SG_ 2333015918 D2M_DCDCChrgeCrrnt_Limt_46 "DCDC当前允许最大充电电流限制";
CM_ SG_ 2333015918 D2M_SUMDATA3_Reserved_46 "预留";
CM_ SG_ 2333015919 D2M_SUMDATA3_CRC_47 "CRC校验";
CM_ SG_ 2333015919 D2M_DCDCLVPowerCurrent_47 "DCDC低压电源电流";
CM_ SG_ 2333015919 D2M_DCDCLVPowerVoltage_47 "DCDC低压电源电压";
CM_ SG_ 2333015919 D2M_DCDCDischrgCrrntLimt_47 "DCDC当前允许最大放电电流限制";
CM_ SG_ 2333015919 D2M_DCDCChrgeCrrnt_Limt_47 "DCDC当前允许最大充电电流限制";
CM_ SG_ 2333015919 D2M_SUMDATA3_Reserved_47 "预留";
CM_ SG_ 2333015920 D2M_SUMDATA3_CRC_48 "CRC校验";
CM_ SG_ 2333015920 D2M_DCDCLVPowerCurrent_48 "DCDC低压电源电流";
CM_ SG_ 2333015920 D2M_DCDCLVPowerVoltage_48 "DCDC低压电源电压";
CM_ SG_ 2333015920 D2M_DCDCDischrgCrrntLimt_48 "DCDC当前允许最大放电电流限制";
CM_ SG_ 2333015920 D2M_DCDCChrgeCrrnt_Limt_48 "DCDC当前允许最大充电电流限制";
CM_ SG_ 2333015920 D2M_SUMDATA3_Reserved_48 "预留";
CM_ SG_ 2333015921 D2M_SUMDATA3_CRC_49 "CRC校验";
CM_ SG_ 2333015921 D2M_DCDCLVPowerCurrent_49 "DCDC低压电源电流";
CM_ SG_ 2333015921 D2M_DCDCLVPowerVoltage_49 "DCDC低压电源电压";
CM_ SG_ 2333015921 D2M_DCDCDischrgCrrntLimt_49 "DCDC当前允许最大放电电流限制";
CM_ SG_ 2333015921 D2M_DCDCChrgeCrrnt_Limt_49 "DCDC当前允许最大充电电流限制";
CM_ SG_ 2333015921 D2M_SUMDATA3_Reserved_49 "预留";
CM_ SG_ 2333015922 D2M_SUMDATA3_CRC_50 "CRC校验";
CM_ SG_ 2333015922 D2M_DCDCLVPowerCurrent_50 "DCDC低压电源电流";
CM_ SG_ 2333015922 D2M_DCDCLVPowerVoltage_50 "DCDC低压电源电压";
CM_ SG_ 2333015922 D2M_DCDCDischrgCrrntLimt_50 "DCDC当前允许最大放电电流限制";
CM_ SG_ 2333015922 D2M_DCDCChrgeCrrnt_Limt_50 "DCDC当前允许最大充电电流限制";
CM_ SG_ 2333015922 D2M_SUMDATA3_Reserved_50 "预留";
CM_ SG_ 2333015923 D2M_SUMDATA3_CRC_51 "CRC校验";
CM_ SG_ 2333015923 D2M_DCDCLVPowerCurrent_51 "DCDC低压电源电流";
CM_ SG_ 2333015923 D2M_DCDCLVPowerVoltage_51 "DCDC低压电源电压";
CM_ SG_ 2333015923 D2M_DCDCDischrgCrrntLimt_51 "DCDC当前允许最大放电电流限制";
CM_ SG_ 2333015923 D2M_DCDCChrgeCrrnt_Limt_51 "DCDC当前允许最大充电电流限制";
CM_ SG_ 2333015923 D2M_SUMDATA3_Reserved_51 "预留";
CM_ SG_ 2333015924 D2M_SUMDATA3_CRC_52 "CRC校验";
CM_ SG_ 2333015924 D2M_DCDCLVPowerCurrent_52 "DCDC低压电源电流";
CM_ SG_ 2333015924 D2M_DCDCLVPowerVoltage_52 "DCDC低压电源电压";
CM_ SG_ 2333015924 D2M_DCDCDischrgCrrntLimt_52 "DCDC当前允许最大放电电流限制";
CM_ SG_ 2333015924 D2M_DCDCChrgeCrrnt_Limt_52 "DCDC当前允许最大充电电流限制";
CM_ SG_ 2333015924 D2M_SUMDATA3_Reserved_52 "预留";
CM_ SG_ 2333015925 D2M_SUMDATA3_CRC_53 "CRC校验";
CM_ SG_ 2333015925 D2M_DCDCLVPowerCurrent_53 "DCDC低压电源电流";
CM_ SG_ 2333015925 D2M_DCDCLVPowerVoltage_53 "DCDC低压电源电压";
CM_ SG_ 2333015925 D2M_DCDCDischrgCrrntLimt_53 "DCDC当前允许最大放电电流限制";
CM_ SG_ 2333015925 D2M_DCDCChrgeCrrnt_Limt_53 "DCDC当前允许最大充电电流限制";
CM_ SG_ 2333015925 D2M_SUMDATA3_Reserved_53 "预留";
CM_ SG_ 2333015926 D2M_SUMDATA3_CRC_54 "CRC校验";
CM_ SG_ 2333015926 D2M_DCDCLVPowerCurrent_54 "DCDC低压电源电流";
CM_ SG_ 2333015926 D2M_DCDCLVPowerVoltage_54 "DCDC低压电源电压";
CM_ SG_ 2333015926 D2M_DCDCDischrgCrrntLimt_54 "DCDC当前允许最大放电电流限制";
CM_ SG_ 2333015926 D2M_DCDCChrgeCrrnt_Limt_54 "DCDC当前允许最大充电电流限制";
CM_ SG_ 2333015926 D2M_SUMDATA3_Reserved_54 "预留";
CM_ SG_ 2333015927 D2M_SUMDATA3_CRC_55 "CRC校验";
CM_ SG_ 2333015927 D2M_DCDCLVPowerCurrent_55 "DCDC低压电源电流";
CM_ SG_ 2333015927 D2M_DCDCLVPowerVoltage_55 "DCDC低压电源电压";
CM_ SG_ 2333015927 D2M_DCDCDischrgCrrntLimt_55 "DCDC当前允许最大放电电流限制";
CM_ SG_ 2333015927 D2M_DCDCChrgeCrrnt_Limt_55 "DCDC当前允许最大充电电流限制";
CM_ SG_ 2333015927 D2M_SUMDATA3_Reserved_55 "预留";
CM_ SG_ 2333015928 D2M_SUMDATA3_CRC_56 "CRC校验";
CM_ SG_ 2333015928 D2M_DCDCLVPowerCurrent_56 "DCDC低压电源电流";
CM_ SG_ 2333015928 D2M_DCDCLVPowerVoltage_56 "DCDC低压电源电压";
CM_ SG_ 2333015928 D2M_DCDCDischrgCrrntLimt_56 "DCDC当前允许最大放电电流限制";
CM_ SG_ 2333015928 D2M_DCDCChrgeCrrnt_Limt_56 "DCDC当前允许最大充电电流限制";
CM_ SG_ 2333015928 D2M_SUMDATA3_Reserved_56 "预留";
CM_ SG_ 2333015929 D2M_SUMDATA3_CRC_57 "CRC校验";
CM_ SG_ 2333015929 D2M_DCDCLVPowerCurrent_57 "DCDC低压电源电流";
CM_ SG_ 2333015929 D2M_DCDCLVPowerVoltage_57 "DCDC低压电源电压";
CM_ SG_ 2333015929 D2M_DCDCDischrgCrrntLimt_57 "DCDC当前允许最大放电电流限制";
CM_ SG_ 2333015929 D2M_DCDCChrgeCrrnt_Limt_57 "DCDC当前允许最大充电电流限制";
CM_ SG_ 2333015929 D2M_SUMDATA3_Reserved_57 "预留";
CM_ SG_ 2333015930 D2M_SUMDATA3_CRC_58 "CRC校验";
CM_ SG_ 2333015930 D2M_DCDCLVPowerCurrent_58 "DCDC低压电源电流";
CM_ SG_ 2333015930 D2M_DCDCLVPowerVoltage_58 "DCDC低压电源电压";
CM_ SG_ 2333015930 D2M_DCDCDischrgCrrntLimt_58 "DCDC当前允许最大放电电流限制";
CM_ SG_ 2333015930 D2M_DCDCChrgeCrrnt_Limt_58 "DCDC当前允许最大充电电流限制";
CM_ SG_ 2333015930 D2M_SUMDATA3_Reserved_58 "预留";
CM_ SG_ 2333015931 D2M_SUMDATA3_CRC_59 "CRC校验";
CM_ SG_ 2333015931 D2M_DCDCLVPowerCurrent_59 "DCDC低压电源电流";
CM_ SG_ 2333015931 D2M_DCDCLVPowerVoltage_59 "DCDC低压电源电压";
CM_ SG_ 2333015931 D2M_DCDCDischrgCrrntLimt_59 "DCDC当前允许最大放电电流限制";
CM_ SG_ 2333015931 D2M_DCDCChrgeCrrnt_Limt_59 "DCDC当前允许最大充电电流限制";
CM_ SG_ 2333015931 D2M_SUMDATA3_Reserved_59 "预留";
CM_ SG_ 2333015932 D2M_SUMDATA3_CRC_60 "CRC校验";
CM_ SG_ 2333015932 D2M_DCDCLVPowerCurrent_60 "DCDC低压电源电流";
CM_ SG_ 2333015932 D2M_DCDCLVPowerVoltage_60 "DCDC低压电源电压";
CM_ SG_ 2333015932 D2M_DCDCDischrgCrrntLimt_60 "DCDC当前允许最大放电电流限制";
CM_ SG_ 2333015932 D2M_DCDCChrgeCrrnt_Limt_60 "DCDC当前允许最大充电电流限制";
CM_ SG_ 2333015932 D2M_SUMDATA3_Reserved_60 "预留";
CM_ SG_ 2333015933 D2M_SUMDATA3_CRC_61 "CRC校验";
CM_ SG_ 2333015933 D2M_DCDCLVPowerCurrent_61 "DCDC低压电源电流";
CM_ SG_ 2333015933 D2M_DCDCLVPowerVoltage_61 "DCDC低压电源电压";
CM_ SG_ 2333015933 D2M_DCDCDischrgCrrntLimt_61 "DCDC当前允许最大放电电流限制";
CM_ SG_ 2333015933 D2M_DCDCChrgeCrrnt_Limt_61 "DCDC当前允许最大充电电流限制";
CM_ SG_ 2333015933 D2M_SUMDATA3_Reserved_61 "预留";
CM_ SG_ 2333015934 D2M_SUMDATA3_CRC_62 "CRC校验";
CM_ SG_ 2333015934 D2M_DCDCLVPowerCurrent_62 "DCDC低压电源电流";
CM_ SG_ 2333015934 D2M_DCDCLVPowerVoltage_62 "DCDC低压电源电压";
CM_ SG_ 2333015934 D2M_DCDCDischrgCrrntLimt_62 "DCDC当前允许最大放电电流限制";
CM_ SG_ 2333015934 D2M_DCDCChrgeCrrnt_Limt_62 "DCDC当前允许最大充电电流限制";
CM_ SG_ 2333015934 D2M_SUMDATA3_Reserved_62 "预留";
CM_ SG_ 2333015935 D2M_SUMDATA3_CRC_63 "CRC校验";
CM_ SG_ 2333015935 D2M_DCDCLVPowerCurrent_63 "DCDC低压电源电流";
CM_ SG_ 2333015935 D2M_DCDCLVPowerVoltage_63 "DCDC低压电源电压";
CM_ SG_ 2333015935 D2M_DCDCDischrgCrrntLimt_63 "DCDC当前允许最大放电电流限制";
CM_ SG_ 2333015935 D2M_DCDCChrgeCrrnt_Limt_63 "DCDC当前允许最大充电电流限制";
CM_ SG_ 2333015935 D2M_SUMDATA3_Reserved_63 "预留";
CM_ SG_ 2333081409 D2M_SUMDATA4_CRC_01 "CRC校验";
CM_ SG_ 2333081409 D2M_DCDC_FaultCode_01 "DCDC故障码";
CM_ SG_ 2333081409 D2M_DCDC_FaultClass_01 "DCDC故障等级";
CM_ SG_ 2333081409 D2M_DCDC_FaultNum_01 "DCDC当前存在的故障数目";
CM_ SG_ 2333081409 D2M_SUMDATA4_Reserved_01 "预留";
CM_ SG_ 2333081410 D2M_SUMDATA4_CRC_02 "CRC校验";
CM_ SG_ 2333081410 D2M_DCDC_FaultCode_02 "DCDC故障码";
CM_ SG_ 2333081410 D2M_DCDC_FaultClass_02 "DCDC故障等级";
CM_ SG_ 2333081410 D2M_DCDC_FaultNum_02 "DCDC当前存在的故障数目";
CM_ SG_ 2333081410 D2M_SUMDATA4_Reserved_02 "预留";
CM_ SG_ 2333081411 D2M_SUMDATA4_CRC_03 "CRC校验";
CM_ SG_ 2333081411 D2M_DCDC_FaultCode_03 "DCDC故障码";
CM_ SG_ 2333081411 D2M_DCDC_FaultClass_03 "DCDC故障等级";
CM_ SG_ 2333081411 D2M_DCDC_FaultNum_03 "DCDC当前存在的故障数目";
CM_ SG_ 2333081411 D2M_SUMDATA4_Reserved_03 "预留";
CM_ SG_ 2333081412 D2M_SUMDATA4_CRC_04 "CRC校验";
CM_ SG_ 2333081412 D2M_DCDC_FaultCode_04 "DCDC故障码";
CM_ SG_ 2333081412 D2M_DCDC_FaultClass_04 "DCDC故障等级";
CM_ SG_ 2333081412 D2M_DCDC_FaultNum_04 "DCDC当前存在的故障数目";
CM_ SG_ 2333081412 D2M_SUMDATA4_Reserved_04 "预留";
CM_ SG_ 2333081413 D2M_SUMDATA4_CRC_05 "CRC校验";
CM_ SG_ 2333081413 D2M_DCDC_FaultCode_05 "DCDC故障码";
CM_ SG_ 2333081413 D2M_DCDC_FaultClass_05 "DCDC故障等级";
CM_ SG_ 2333081413 D2M_DCDC_FaultNum_05 "DCDC当前存在的故障数目";
CM_ SG_ 2333081413 D2M_SUMDATA4_Reserved_05 "预留";
CM_ SG_ 2333081414 D2M_SUMDATA4_CRC_06 "CRC校验";
CM_ SG_ 2333081414 D2M_DCDC_FaultCode_06 "DCDC故障码";
CM_ SG_ 2333081414 D2M_DCDC_FaultClass_06 "DCDC故障等级";
CM_ SG_ 2333081414 D2M_DCDC_FaultNum_06 "DCDC当前存在的故障数目";
CM_ SG_ 2333081414 D2M_SUMDATA4_Reserved_06 "预留";
CM_ SG_ 2333081415 D2M_SUMDATA4_CRC_07 "CRC校验";
CM_ SG_ 2333081415 D2M_DCDC_FaultCode_07 "DCDC故障码";
CM_ SG_ 2333081415 D2M_DCDC_FaultClass_07 "DCDC故障等级";
CM_ SG_ 2333081415 D2M_DCDC_FaultNum_07 "DCDC当前存在的故障数目";
CM_ SG_ 2333081415 D2M_SUMDATA4_Reserved_07 "预留";
CM_ SG_ 2333081416 D2M_SUMDATA4_CRC_08 "CRC校验";
CM_ SG_ 2333081416 D2M_DCDC_FaultCode_08 "DCDC故障码";
CM_ SG_ 2333081416 D2M_DCDC_FaultClass_08 "DCDC故障等级";
CM_ SG_ 2333081416 D2M_DCDC_FaultNum_08 "DCDC当前存在的故障数目";
CM_ SG_ 2333081416 D2M_SUMDATA4_Reserved_08 "预留";
CM_ SG_ 2333081417 D2M_SUMDATA4_CRC_09 "CRC校验";
CM_ SG_ 2333081417 D2M_DCDC_FaultCode_09 "DCDC故障码";
CM_ SG_ 2333081417 D2M_DCDC_FaultClass_09 "DCDC故障等级";
CM_ SG_ 2333081417 D2M_DCDC_FaultNum_09 "DCDC当前存在的故障数目";
CM_ SG_ 2333081417 D2M_SUMDATA4_Reserved_09 "预留";
CM_ SG_ 2333081418 D2M_SUMDATA4_CRC_10 "CRC校验";
CM_ SG_ 2333081418 D2M_DCDC_FaultCode_10 "DCDC故障码";
CM_ SG_ 2333081418 D2M_DCDC_FaultClass_10 "DCDC故障等级";
CM_ SG_ 2333081418 D2M_DCDC_FaultNum_10 "DCDC当前存在的故障数目";
CM_ SG_ 2333081418 D2M_SUMDATA4_Reserved_10 "预留";
CM_ SG_ 2333081419 D2M_SUMDATA4_CRC_11 "CRC校验";
CM_ SG_ 2333081419 D2M_DCDC_FaultCode_11 "DCDC故障码";
CM_ SG_ 2333081419 D2M_DCDC_FaultClass_11 "DCDC故障等级";
CM_ SG_ 2333081419 D2M_DCDC_FaultNum_11 "DCDC当前存在的故障数目";
CM_ SG_ 2333081419 D2M_SUMDATA4_Reserved_11 "预留";
CM_ SG_ 2333081420 D2M_SUMDATA4_CRC_12 "CRC校验";
CM_ SG_ 2333081420 D2M_DCDC_FaultCode_12 "DCDC故障码";
CM_ SG_ 2333081420 D2M_DCDC_FaultClass_12 "DCDC故障等级";
CM_ SG_ 2333081420 D2M_DCDC_FaultNum_12 "DCDC当前存在的故障数目";
CM_ SG_ 2333081420 D2M_SUMDATA4_Reserved_12 "预留";
CM_ SG_ 2333081421 D2M_SUMDATA4_CRC_13 "CRC校验";
CM_ SG_ 2333081421 D2M_DCDC_FaultCode_13 "DCDC故障码";
CM_ SG_ 2333081421 D2M_DCDC_FaultClass_13 "DCDC故障等级";
CM_ SG_ 2333081421 D2M_DCDC_FaultNum_13 "DCDC当前存在的故障数目";
CM_ SG_ 2333081421 D2M_SUMDATA4_Reserved_13 "预留";
CM_ SG_ 2333081422 D2M_SUMDATA4_CRC_14 "CRC校验";
CM_ SG_ 2333081422 D2M_DCDC_FaultCode_14 "DCDC故障码";
CM_ SG_ 2333081422 D2M_DCDC_FaultClass_14 "DCDC故障等级";
CM_ SG_ 2333081422 D2M_DCDC_FaultNum_14 "DCDC当前存在的故障数目";
CM_ SG_ 2333081422 D2M_SUMDATA4_Reserved_14 "预留";
CM_ SG_ 2333081423 D2M_SUMDATA4_CRC_15 "CRC校验";
CM_ SG_ 2333081423 D2M_DCDC_FaultCode_15 "DCDC故障码";
CM_ SG_ 2333081423 D2M_DCDC_FaultClass_15 "DCDC故障等级";
CM_ SG_ 2333081423 D2M_DCDC_FaultNum_15 "DCDC当前存在的故障数目";
CM_ SG_ 2333081423 D2M_SUMDATA4_Reserved_15 "预留";
CM_ SG_ 2333081424 D2M_SUMDATA4_CRC_16 "CRC校验";
CM_ SG_ 2333081424 D2M_DCDC_FaultCode_16 "DCDC故障码";
CM_ SG_ 2333081424 D2M_DCDC_FaultClass_16 "DCDC故障等级";
CM_ SG_ 2333081424 D2M_DCDC_FaultNum_16 "DCDC当前存在的故障数目";
CM_ SG_ 2333081424 D2M_SUMDATA4_Reserved_16 "预留";
CM_ SG_ 2333081425 D2M_SUMDATA4_CRC_17 "CRC校验";
CM_ SG_ 2333081425 D2M_DCDC_FaultCode_17 "DCDC故障码";
CM_ SG_ 2333081425 D2M_DCDC_FaultClass_17 "DCDC故障等级";
CM_ SG_ 2333081425 D2M_DCDC_FaultNum_17 "DCDC当前存在的故障数目";
CM_ SG_ 2333081425 D2M_SUMDATA4_Reserved_17 "预留";
CM_ SG_ 2333081426 D2M_SUMDATA4_CRC_18 "CRC校验";
CM_ SG_ 2333081426 D2M_DCDC_FaultCode_18 "DCDC故障码";
CM_ SG_ 2333081426 D2M_DCDC_FaultClass_18 "DCDC故障等级";
CM_ SG_ 2333081426 D2M_DCDC_FaultNum_18 "DCDC当前存在的故障数目";
CM_ SG_ 2333081426 D2M_SUMDATA4_Reserved_18 "预留";
CM_ SG_ 2333081427 D2M_SUMDATA4_CRC_19 "CRC校验";
CM_ SG_ 2333081427 D2M_DCDC_FaultCode_19 "DCDC故障码";
CM_ SG_ 2333081427 D2M_DCDC_FaultClass_19 "DCDC故障等级";
CM_ SG_ 2333081427 D2M_DCDC_FaultNum_19 "DCDC当前存在的故障数目";
CM_ SG_ 2333081427 D2M_SUMDATA4_Reserved_19 "预留";
CM_ SG_ 2333081428 D2M_SUMDATA4_CRC_20 "CRC校验";
CM_ SG_ 2333081428 D2M_DCDC_FaultCode_20 "DCDC故障码";
CM_ SG_ 2333081428 D2M_DCDC_FaultClass_20 "DCDC故障等级";
CM_ SG_ 2333081428 D2M_DCDC_FaultNum_20 "DCDC当前存在的故障数目";
CM_ SG_ 2333081428 D2M_SUMDATA4_Reserved_20 "预留";
CM_ SG_ 2333081429 D2M_SUMDATA4_CRC_21 "CRC校验";
CM_ SG_ 2333081429 D2M_DCDC_FaultCode_21 "DCDC故障码";
CM_ SG_ 2333081429 D2M_DCDC_FaultClass_21 "DCDC故障等级";
CM_ SG_ 2333081429 D2M_DCDC_FaultNum_21 "DCDC当前存在的故障数目";
CM_ SG_ 2333081429 D2M_SUMDATA4_Reserved_21 "预留";
CM_ SG_ 2333081430 D2M_SUMDATA4_CRC_22 "CRC校验";
CM_ SG_ 2333081430 D2M_DCDC_FaultCode_22 "DCDC故障码";
CM_ SG_ 2333081430 D2M_DCDC_FaultClass_22 "DCDC故障等级";
CM_ SG_ 2333081430 D2M_DCDC_FaultNum_22 "DCDC当前存在的故障数目";
CM_ SG_ 2333081430 D2M_SUMDATA4_Reserved_22 "预留";
CM_ SG_ 2333081431 D2M_SUMDATA4_CRC_23 "CRC校验";
CM_ SG_ 2333081431 D2M_DCDC_FaultCode_23 "DCDC故障码";
CM_ SG_ 2333081431 D2M_DCDC_FaultClass_23 "DCDC故障等级";
CM_ SG_ 2333081431 D2M_DCDC_FaultNum_23 "DCDC当前存在的故障数目";
CM_ SG_ 2333081431 D2M_SUMDATA4_Reserved_23 "预留";
CM_ SG_ 2333081432 D2M_SUMDATA4_CRC_24 "CRC校验";
CM_ SG_ 2333081432 D2M_DCDC_FaultCode_24 "DCDC故障码";
CM_ SG_ 2333081432 D2M_DCDC_FaultClass_24 "DCDC故障等级";
CM_ SG_ 2333081432 D2M_DCDC_FaultNum_24 "DCDC当前存在的故障数目";
CM_ SG_ 2333081432 D2M_SUMDATA4_Reserved_24 "预留";
CM_ SG_ 2333081433 D2M_SUMDATA4_CRC_25 "CRC校验";
CM_ SG_ 2333081433 D2M_DCDC_FaultCode_25 "DCDC故障码";
CM_ SG_ 2333081433 D2M_DCDC_FaultClass_25 "DCDC故障等级";
CM_ SG_ 2333081433 D2M_DCDC_FaultNum_25 "DCDC当前存在的故障数目";
CM_ SG_ 2333081433 D2M_SUMDATA4_Reserved_25 "预留";
CM_ SG_ 2333081434 D2M_SUMDATA4_CRC_26 "CRC校验";
CM_ SG_ 2333081434 D2M_DCDC_FaultCode_26 "DCDC故障码";
CM_ SG_ 2333081434 D2M_DCDC_FaultClass_26 "DCDC故障等级";
CM_ SG_ 2333081434 D2M_DCDC_FaultNum_26 "DCDC当前存在的故障数目";
CM_ SG_ 2333081434 D2M_SUMDATA4_Reserved_26 "预留";
CM_ SG_ 2333081435 D2M_SUMDATA4_CRC_27 "CRC校验";
CM_ SG_ 2333081435 D2M_DCDC_FaultCode_27 "DCDC故障码";
CM_ SG_ 2333081435 D2M_DCDC_FaultClass_27 "DCDC故障等级";
CM_ SG_ 2333081435 D2M_DCDC_FaultNum_27 "DCDC当前存在的故障数目";
CM_ SG_ 2333081435 D2M_SUMDATA4_Reserved_27 "预留";
CM_ SG_ 2333081436 D2M_SUMDATA4_CRC_28 "CRC校验";
CM_ SG_ 2333081436 D2M_DCDC_FaultCode_28 "DCDC故障码";
CM_ SG_ 2333081436 D2M_DCDC_FaultClass_28 "DCDC故障等级";
CM_ SG_ 2333081436 D2M_DCDC_FaultNum_28 "DCDC当前存在的故障数目";
CM_ SG_ 2333081436 D2M_SUMDATA4_Reserved_28 "预留";
CM_ SG_ 2333081437 D2M_SUMDATA4_CRC_29 "CRC校验";
CM_ SG_ 2333081437 D2M_DCDC_FaultCode_29 "DCDC故障码";
CM_ SG_ 2333081437 D2M_DCDC_FaultClass_29 "DCDC故障等级";
CM_ SG_ 2333081437 D2M_DCDC_FaultNum_29 "DCDC当前存在的故障数目";
CM_ SG_ 2333081437 D2M_SUMDATA4_Reserved_29 "预留";
CM_ SG_ 2333081438 D2M_SUMDATA4_CRC_30 "CRC校验";
CM_ SG_ 2333081438 D2M_DCDC_FaultCode_30 "DCDC故障码";
CM_ SG_ 2333081438 D2M_DCDC_FaultClass_30 "DCDC故障等级";
CM_ SG_ 2333081438 D2M_DCDC_FaultNum_30 "DCDC当前存在的故障数目";
CM_ SG_ 2333081438 D2M_SUMDATA4_Reserved_30 "预留";
CM_ SG_ 2333081439 D2M_SUMDATA4_CRC_31 "CRC校验";
CM_ SG_ 2333081439 D2M_DCDC_FaultCode_31 "DCDC故障码";
CM_ SG_ 2333081439 D2M_DCDC_FaultClass_31 "DCDC故障等级";
CM_ SG_ 2333081439 D2M_DCDC_FaultNum_31 "DCDC当前存在的故障数目";
CM_ SG_ 2333081439 D2M_SUMDATA4_Reserved_31 "预留";
CM_ SG_ 2333081440 D2M_SUMDATA4_CRC_32 "CRC校验";
CM_ SG_ 2333081440 D2M_DCDC_FaultCode_32 "DCDC故障码";
CM_ SG_ 2333081440 D2M_DCDC_FaultClass_32 "DCDC故障等级";
CM_ SG_ 2333081440 D2M_DCDC_FaultNum_32 "DCDC当前存在的故障数目";
CM_ SG_ 2333081440 D2M_SUMDATA4_Reserved_32 "预留";
CM_ SG_ 2333081441 D2M_SUMDATA4_CRC_33 "CRC校验";
CM_ SG_ 2333081441 D2M_DCDC_FaultCode_33 "DCDC故障码";
CM_ SG_ 2333081441 D2M_DCDC_FaultClass_33 "DCDC故障等级";
CM_ SG_ 2333081441 D2M_DCDC_FaultNum_33 "DCDC当前存在的故障数目";
CM_ SG_ 2333081441 D2M_SUMDATA4_Reserved_33 "预留";
CM_ SG_ 2333081442 D2M_SUMDATA4_CRC_34 "CRC校验";
CM_ SG_ 2333081442 D2M_DCDC_FaultCode_34 "DCDC故障码";
CM_ SG_ 2333081442 D2M_DCDC_FaultClass_34 "DCDC故障等级";
CM_ SG_ 2333081442 D2M_DCDC_FaultNum_34 "DCDC当前存在的故障数目";
CM_ SG_ 2333081442 D2M_SUMDATA4_Reserved_34 "预留";
CM_ SG_ 2333081443 D2M_SUMDATA4_CRC_35 "CRC校验";
CM_ SG_ 2333081443 D2M_DCDC_FaultCode_35 "DCDC故障码";
CM_ SG_ 2333081443 D2M_DCDC_FaultClass_35 "DCDC故障等级";
CM_ SG_ 2333081443 D2M_DCDC_FaultNum_35 "DCDC当前存在的故障数目";
CM_ SG_ 2333081443 D2M_SUMDATA4_Reserved_35 "预留";
CM_ SG_ 2333081444 D2M_SUMDATA4_CRC_36 "CRC校验";
CM_ SG_ 2333081444 D2M_DCDC_FaultCode_36 "DCDC故障码";
CM_ SG_ 2333081444 D2M_DCDC_FaultClass_36 "DCDC故障等级";
CM_ SG_ 2333081444 D2M_DCDC_FaultNum_36 "DCDC当前存在的故障数目";
CM_ SG_ 2333081444 D2M_SUMDATA4_Reserved_36 "预留";
CM_ SG_ 2333081445 D2M_SUMDATA4_CRC_37 "CRC校验";
CM_ SG_ 2333081445 D2M_DCDC_FaultCode_37 "DCDC故障码";
CM_ SG_ 2333081445 D2M_DCDC_FaultClass_37 "DCDC故障等级";
CM_ SG_ 2333081445 D2M_DCDC_FaultNum_37 "DCDC当前存在的故障数目";
CM_ SG_ 2333081445 D2M_SUMDATA4_Reserved_37 "预留";
CM_ SG_ 2333081446 D2M_SUMDATA4_CRC_38 "CRC校验";
CM_ SG_ 2333081446 D2M_DCDC_FaultCode_38 "DCDC故障码";
CM_ SG_ 2333081446 D2M_DCDC_FaultClass_38 "DCDC故障等级";
CM_ SG_ 2333081446 D2M_DCDC_FaultNum_38 "DCDC当前存在的故障数目";
CM_ SG_ 2333081446 D2M_SUMDATA4_Reserved_38 "预留";
CM_ SG_ 2333081447 D2M_SUMDATA4_CRC_39 "CRC校验";
CM_ SG_ 2333081447 D2M_DCDC_FaultCode_39 "DCDC故障码";
CM_ SG_ 2333081447 D2M_DCDC_FaultClass_39 "DCDC故障等级";
CM_ SG_ 2333081447 D2M_DCDC_FaultNum_39 "DCDC当前存在的故障数目";
CM_ SG_ 2333081447 D2M_SUMDATA4_Reserved_39 "预留";
CM_ SG_ 2333081448 D2M_SUMDATA4_CRC_40 "CRC校验";
CM_ SG_ 2333081448 D2M_DCDC_FaultCode_40 "DCDC故障码";
CM_ SG_ 2333081448 D2M_DCDC_FaultClass_40 "DCDC故障等级";
CM_ SG_ 2333081448 D2M_DCDC_FaultNum_40 "DCDC当前存在的故障数目";
CM_ SG_ 2333081448 D2M_SUMDATA4_Reserved_40 "预留";
CM_ SG_ 2333081449 D2M_SUMDATA4_CRC_41 "CRC校验";
CM_ SG_ 2333081449 D2M_DCDC_FaultCode_41 "DCDC故障码";
CM_ SG_ 2333081449 D2M_DCDC_FaultClass_41 "DCDC故障等级";
CM_ SG_ 2333081449 D2M_DCDC_FaultNum_41 "DCDC当前存在的故障数目";
CM_ SG_ 2333081449 D2M_SUMDATA4_Reserved_41 "预留";
CM_ SG_ 2333081450 D2M_SUMDATA4_CRC_42 "CRC校验";
CM_ SG_ 2333081450 D2M_DCDC_FaultCode_42 "DCDC故障码";
CM_ SG_ 2333081450 D2M_DCDC_FaultClass_42 "DCDC故障等级";
CM_ SG_ 2333081450 D2M_DCDC_FaultNum_42 "DCDC当前存在的故障数目";
CM_ SG_ 2333081450 D2M_SUMDATA4_Reserved_42 "预留";
CM_ SG_ 2333081451 D2M_SUMDATA4_CRC_43 "CRC校验";
CM_ SG_ 2333081451 D2M_DCDC_FaultCode_43 "DCDC故障码";
CM_ SG_ 2333081451 D2M_DCDC_FaultClass_43 "DCDC故障等级";
CM_ SG_ 2333081451 D2M_DCDC_FaultNum_43 "DCDC当前存在的故障数目";
CM_ SG_ 2333081451 D2M_SUMDATA4_Reserved_43 "预留";
CM_ SG_ 2333081452 D2M_SUMDATA4_CRC_44 "CRC校验";
CM_ SG_ 2333081452 D2M_DCDC_FaultCode_44 "DCDC故障码";
CM_ SG_ 2333081452 D2M_DCDC_FaultClass_44 "DCDC故障等级";
CM_ SG_ 2333081452 D2M_DCDC_FaultNum_44 "DCDC当前存在的故障数目";
CM_ SG_ 2333081452 D2M_SUMDATA4_Reserved_44 "预留";
CM_ SG_ 2333081453 D2M_SUMDATA4_CRC_45 "CRC校验";
CM_ SG_ 2333081453 D2M_DCDC_FaultCode_45 "DCDC故障码";
CM_ SG_ 2333081453 D2M_DCDC_FaultClass_45 "DCDC故障等级";
CM_ SG_ 2333081453 D2M_DCDC_FaultNum_45 "DCDC当前存在的故障数目";
CM_ SG_ 2333081453 D2M_SUMDATA4_Reserved_45 "预留";
CM_ SG_ 2333081454 D2M_SUMDATA4_CRC_46 "CRC校验";
CM_ SG_ 2333081454 D2M_DCDC_FaultCode_46 "DCDC故障码";
CM_ SG_ 2333081454 D2M_DCDC_FaultClass_46 "DCDC故障等级";
CM_ SG_ 2333081454 D2M_DCDC_FaultNum_46 "DCDC当前存在的故障数目";
CM_ SG_ 2333081454 D2M_SUMDATA4_Reserved_46 "预留";
CM_ SG_ 2333081455 D2M_SUMDATA4_CRC_47 "CRC校验";
CM_ SG_ 2333081455 D2M_DCDC_FaultCode_47 "DCDC故障码";
CM_ SG_ 2333081455 D2M_DCDC_FaultClass_47 "DCDC故障等级";
CM_ SG_ 2333081455 D2M_DCDC_FaultNum_47 "DCDC当前存在的故障数目";
CM_ SG_ 2333081455 D2M_SUMDATA4_Reserved_47 "预留";
CM_ SG_ 2333081456 D2M_SUMDATA4_CRC_48 "CRC校验";
CM_ SG_ 2333081456 D2M_DCDC_FaultCode_48 "DCDC故障码";
CM_ SG_ 2333081456 D2M_DCDC_FaultClass_48 "DCDC故障等级";
CM_ SG_ 2333081456 D2M_DCDC_FaultNum_48 "DCDC当前存在的故障数目";
CM_ SG_ 2333081456 D2M_SUMDATA4_Reserved_48 "预留";
CM_ SG_ 2333081457 D2M_SUMDATA4_CRC_49 "CRC校验";
CM_ SG_ 2333081457 D2M_DCDC_FaultCode_49 "DCDC故障码";
CM_ SG_ 2333081457 D2M_DCDC_FaultClass_49 "DCDC故障等级";
CM_ SG_ 2333081457 D2M_DCDC_FaultNum_49 "DCDC当前存在的故障数目";
CM_ SG_ 2333081457 D2M_SUMDATA4_Reserved_49 "预留";
CM_ SG_ 2333081458 D2M_SUMDATA4_CRC_50 "CRC校验";
CM_ SG_ 2333081458 D2M_DCDC_FaultCode_50 "DCDC故障码";
CM_ SG_ 2333081458 D2M_DCDC_FaultClass_50 "DCDC故障等级";
CM_ SG_ 2333081458 D2M_DCDC_FaultNum_50 "DCDC当前存在的故障数目";
CM_ SG_ 2333081458 D2M_SUMDATA4_Reserved_50 "预留";
CM_ SG_ 2333081459 D2M_SUMDATA4_CRC_51 "CRC校验";
CM_ SG_ 2333081459 D2M_DCDC_FaultCode_51 "DCDC故障码";
CM_ SG_ 2333081459 D2M_DCDC_FaultClass_51 "DCDC故障等级";
CM_ SG_ 2333081459 D2M_DCDC_FaultNum_51 "DCDC当前存在的故障数目";
CM_ SG_ 2333081459 D2M_SUMDATA4_Reserved_51 "预留";
CM_ SG_ 2333081460 D2M_SUMDATA4_CRC_52 "CRC校验";
CM_ SG_ 2333081460 D2M_DCDC_FaultCode_52 "DCDC故障码";
CM_ SG_ 2333081460 D2M_DCDC_FaultClass_52 "DCDC故障等级";
CM_ SG_ 2333081460 D2M_DCDC_FaultNum_52 "DCDC当前存在的故障数目";
CM_ SG_ 2333081460 D2M_SUMDATA4_Reserved_52 "预留";
CM_ SG_ 2333081461 D2M_SUMDATA4_CRC_53 "CRC校验";
CM_ SG_ 2333081461 D2M_DCDC_FaultCode_53 "DCDC故障码";
CM_ SG_ 2333081461 D2M_DCDC_FaultClass_53 "DCDC故障等级";
CM_ SG_ 2333081461 D2M_DCDC_FaultNum_53 "DCDC当前存在的故障数目";
CM_ SG_ 2333081461 D2M_SUMDATA4_Reserved_53 "预留";
CM_ SG_ 2333081462 D2M_SUMDATA4_CRC_54 "CRC校验";
CM_ SG_ 2333081462 D2M_DCDC_FaultCode_54 "DCDC故障码";
CM_ SG_ 2333081462 D2M_DCDC_FaultClass_54 "DCDC故障等级";
CM_ SG_ 2333081462 D2M_DCDC_FaultNum_54 "DCDC当前存在的故障数目";
CM_ SG_ 2333081462 D2M_SUMDATA4_Reserved_54 "预留";
CM_ SG_ 2333081463 D2M_SUMDATA4_CRC_55 "CRC校验";
CM_ SG_ 2333081463 D2M_DCDC_FaultCode_55 "DCDC故障码";
CM_ SG_ 2333081463 D2M_DCDC_FaultClass_55 "DCDC故障等级";
CM_ SG_ 2333081463 D2M_DCDC_FaultNum_55 "DCDC当前存在的故障数目";
CM_ SG_ 2333081463 D2M_SUMDATA4_Reserved_55 "预留";
CM_ SG_ 2333081464 D2M_SUMDATA4_CRC_56 "CRC校验";
CM_ SG_ 2333081464 D2M_DCDC_FaultCode_56 "DCDC故障码";
CM_ SG_ 2333081464 D2M_DCDC_FaultClass_56 "DCDC故障等级";
CM_ SG_ 2333081464 D2M_DCDC_FaultNum_56 "DCDC当前存在的故障数目";
CM_ SG_ 2333081464 D2M_SUMDATA4_Reserved_56 "预留";
CM_ SG_ 2333081465 D2M_SUMDATA4_CRC_57 "CRC校验";
CM_ SG_ 2333081465 D2M_DCDC_FaultCode_57 "DCDC故障码";
CM_ SG_ 2333081465 D2M_DCDC_FaultClass_57 "DCDC故障等级";
CM_ SG_ 2333081465 D2M_DCDC_FaultNum_57 "DCDC当前存在的故障数目";
CM_ SG_ 2333081465 D2M_SUMDATA4_Reserved_57 "预留";
CM_ SG_ 2333081466 D2M_SUMDATA4_CRC_58 "CRC校验";
CM_ SG_ 2333081466 D2M_DCDC_FaultCode_58 "DCDC故障码";
CM_ SG_ 2333081466 D2M_DCDC_FaultClass_58 "DCDC故障等级";
CM_ SG_ 2333081466 D2M_DCDC_FaultNum_58 "DCDC当前存在的故障数目";
CM_ SG_ 2333081466 D2M_SUMDATA4_Reserved_58 "预留";
CM_ SG_ 2333081467 D2M_SUMDATA4_CRC_59 "CRC校验";
CM_ SG_ 2333081467 D2M_DCDC_FaultCode_59 "DCDC故障码";
CM_ SG_ 2333081467 D2M_DCDC_FaultClass_59 "DCDC故障等级";
CM_ SG_ 2333081467 D2M_DCDC_FaultNum_59 "DCDC当前存在的故障数目";
CM_ SG_ 2333081467 D2M_SUMDATA4_Reserved_59 "预留";
CM_ SG_ 2333081468 D2M_SUMDATA4_CRC_60 "CRC校验";
CM_ SG_ 2333081468 D2M_DCDC_FaultCode_60 "DCDC故障码";
CM_ SG_ 2333081468 D2M_DCDC_FaultClass_60 "DCDC故障等级";
CM_ SG_ 2333081468 D2M_DCDC_FaultNum_60 "DCDC当前存在的故障数目";
CM_ SG_ 2333081468 D2M_SUMDATA4_Reserved_60 "预留";
CM_ SG_ 2333081469 D2M_SUMDATA4_CRC_61 "CRC校验";
CM_ SG_ 2333081469 D2M_DCDC_FaultCode_61 "DCDC故障码";
CM_ SG_ 2333081469 D2M_DCDC_FaultClass_61 "DCDC故障等级";
CM_ SG_ 2333081469 D2M_DCDC_FaultNum_61 "DCDC当前存在的故障数目";
CM_ SG_ 2333081469 D2M_SUMDATA4_Reserved_61 "预留";
CM_ SG_ 2333081470 D2M_SUMDATA4_CRC_62 "CRC校验";
CM_ SG_ 2333081470 D2M_DCDC_FaultCode_62 "DCDC故障码";
CM_ SG_ 2333081470 D2M_DCDC_FaultClass_62 "DCDC故障等级";
CM_ SG_ 2333081470 D2M_DCDC_FaultNum_62 "DCDC当前存在的故障数目";
CM_ SG_ 2333081470 D2M_SUMDATA4_Reserved_62 "预留";
CM_ SG_ 2333081471 D2M_SUMDATA4_CRC_63 "CRC校验";
CM_ SG_ 2333081471 D2M_DCDC_FaultCode_63 "DCDC故障码";
CM_ SG_ 2333081471 D2M_DCDC_FaultClass_63 "DCDC故障等级";
CM_ SG_ 2333081471 D2M_DCDC_FaultNum_63 "DCDC当前存在的故障数目";
CM_ SG_ 2333081471 D2M_SUMDATA4_Reserved_63 "预留";
CM_ SG_ 2149416769 P2D_CMD2_CRC_01 "预留 （这里没必要做CRC校验吧？）";
CM_ SG_ 2149416769 P2D_CMD2_DCDCSerialNum_01 "预留（原为DCDC编号）";
CM_ SG_ 2149416769 P2D_CMD2_DCDCEnable_01 "使能DCDC命令";
CM_ SG_ 2149416769 P2D_CMD2_Reserved1_01 "预留1";
CM_ SG_ 2149416769 P2D_CMD2_DCDCWrkMdSwtch_01 "DCDC工作状态切换";
CM_ SG_ 2149416769 P2D_CMD2_DCDCWrkMdSet_01 "DCDC工作模式设定";
CM_ SG_ 2149416769 P2D_CMD2_Reserved2_01 "预留2";
CM_ SG_ 2149416769 P2D_CMD2_DCDCOutputCrrntSet_01 "电池电流设定（放正充负）
电池电流=DC低压端电流+DC高压端电流";
CM_ SG_ 2149416769 P2D_CMD2_DCDCOutputVltg_Set_01 "DCDC输出电压设定";
CM_ SG_ 2149416769 P2D_CMD2_Reserved3_01 "预留3";
CM_ SG_ 2149416769 P2D_CMD2_CommunicationState_01 "PC与DCDC通讯状态";
CM_ SG_ 2149416769 P2D_CMD2_DCDC_Fault_Clear_01 "DCDC故障清除指令";
CM_ SG_ 2149416769 P2D_CMD2_PCSOperationState_01 "PCS运行状态（预留）";
CM_ SG_ 2149416769 P2D_CMD2_DCDCLVoffControl_01 "DCDC低压下电控制";
CM_ SG_ 2149416769 P2D_CMD2_Reserved4_01 "预留4";
CM_ SG_ 2149416770 P2D_CMD2_CRC_02 "预留 （这里没必要做CRC校验吧？）";
CM_ SG_ 2149416770 P2D_CMD2_DCDCSerialNum_02 "预留（原为DCDC编号）";
CM_ SG_ 2149416770 P2D_CMD2_DCDCEnable_02 "使能DCDC命令";
CM_ SG_ 2149416770 P2D_CMD2_Reserved1_02 "预留1";
CM_ SG_ 2149416770 P2D_CMD2_DCDCWrkMdSwtch_02 "DCDC工作状态切换";
CM_ SG_ 2149416770 P2D_CMD2_DCDCWrkMdSet_02 "DCDC工作模式设定";
CM_ SG_ 2149416770 P2D_CMD2_Reserved2_02 "预留2";
CM_ SG_ 2149416770 P2D_CMD2_DCDCOutputCrrntSet_02 "电池电流设定（放正充负）
电池电流=DC低压端电流+DC高压端电流";
CM_ SG_ 2149416770 P2D_CMD2_DCDCOutputVltg_Set_02 "DCDC输出电压设定";
CM_ SG_ 2149416770 P2D_CMD2_Reserved3_02 "预留3";
CM_ SG_ 2149416770 P2D_CMD2_CommunicationState_02 "PC与DCDC通讯状态";
CM_ SG_ 2149416770 P2D_CMD2_DCDC_Fault_Clear_02 "DCDC故障清除指令";
CM_ SG_ 2149416770 P2D_CMD2_PCSOperationState_02 "PCS运行状态（预留）";
CM_ SG_ 2149416770 P2D_CMD2_DCDCLVoffControl_02 "DCDC低压下电控制";
CM_ SG_ 2149416770 P2D_CMD2_Reserved4_02 "预留4";
CM_ SG_ 2149416771 P2D_CMD2_CRC_03 "预留 （这里没必要做CRC校验吧？）";
CM_ SG_ 2149416771 P2D_CMD2_DCDCSerialNum_03 "预留（原为DCDC编号）";
CM_ SG_ 2149416771 P2D_CMD2_DCDCEnable_03 "使能DCDC命令";
CM_ SG_ 2149416771 P2D_CMD2_Reserved1_03 "预留1";
CM_ SG_ 2149416771 P2D_CMD2_DCDCWrkMdSwtch_03 "DCDC工作状态切换";
CM_ SG_ 2149416771 P2D_CMD2_DCDCWrkMdSet_03 "DCDC工作模式设定";
CM_ SG_ 2149416771 P2D_CMD2_Reserved2_03 "预留2";
CM_ SG_ 2149416771 P2D_CMD2_DCDCOutputCrrntSet_03 "电池电流设定（放正充负）
电池电流=DC低压端电流+DC高压端电流";
CM_ SG_ 2149416771 P2D_CMD2_DCDCOutputVltg_Set_03 "DCDC输出电压设定";
CM_ SG_ 2149416771 P2D_CMD2_Reserved3_03 "预留3";
CM_ SG_ 2149416771 P2D_CMD2_CommunicationState_03 "PC与DCDC通讯状态";
CM_ SG_ 2149416771 P2D_CMD2_DCDC_Fault_Clear_03 "DCDC故障清除指令";
CM_ SG_ 2149416771 P2D_CMD2_PCSOperationState_03 "PCS运行状态（预留）";
CM_ SG_ 2149416771 P2D_CMD2_DCDCLVoffControl_03 "DCDC低压下电控制";
CM_ SG_ 2149416771 P2D_CMD2_Reserved4_03 "预留4";
CM_ SG_ 2149416772 P2D_CMD2_CRC_04 "预留 （这里没必要做CRC校验吧？）";
CM_ SG_ 2149416772 P2D_CMD2_DCDCSerialNum_04 "预留（原为DCDC编号）";
CM_ SG_ 2149416772 P2D_CMD2_DCDCEnable_04 "使能DCDC命令";
CM_ SG_ 2149416772 P2D_CMD2_Reserved1_04 "预留1";
CM_ SG_ 2149416772 P2D_CMD2_DCDCWrkMdSwtch_04 "DCDC工作状态切换";
CM_ SG_ 2149416772 P2D_CMD2_DCDCWrkMdSet_04 "DCDC工作模式设定";
CM_ SG_ 2149416772 P2D_CMD2_Reserved2_04 "预留2";
CM_ SG_ 2149416772 P2D_CMD2_DCDCOutputCrrntSet_04 "电池电流设定（放正充负）
电池电流=DC低压端电流+DC高压端电流";
CM_ SG_ 2149416772 P2D_CMD2_DCDCOutputVltg_Set_04 "DCDC输出电压设定";
CM_ SG_ 2149416772 P2D_CMD2_Reserved3_04 "预留3";
CM_ SG_ 2149416772 P2D_CMD2_CommunicationState_04 "PC与DCDC通讯状态";
CM_ SG_ 2149416772 P2D_CMD2_DCDC_Fault_Clear_04 "DCDC故障清除指令";
CM_ SG_ 2149416772 P2D_CMD2_PCSOperationState_04 "PCS运行状态（预留）";
CM_ SG_ 2149416772 P2D_CMD2_DCDCLVoffControl_04 "DCDC低压下电控制";
CM_ SG_ 2149416772 P2D_CMD2_Reserved4_04 "预留4";
CM_ SG_ 2149416773 P2D_CMD2_CRC_05 "预留 （这里没必要做CRC校验吧？）";
CM_ SG_ 2149416773 P2D_CMD2_DCDCSerialNum_05 "预留（原为DCDC编号）";
CM_ SG_ 2149416773 P2D_CMD2_DCDCEnable_05 "使能DCDC命令";
CM_ SG_ 2149416773 P2D_CMD2_Reserved1_05 "预留1";
CM_ SG_ 2149416773 P2D_CMD2_DCDCWrkMdSwtch_05 "DCDC工作状态切换";
CM_ SG_ 2149416773 P2D_CMD2_DCDCWrkMdSet_05 "DCDC工作模式设定";
CM_ SG_ 2149416773 P2D_CMD2_Reserved2_05 "预留2";
CM_ SG_ 2149416773 P2D_CMD2_DCDCOutputCrrntSet_05 "电池电流设定（放正充负）
电池电流=DC低压端电流+DC高压端电流";
CM_ SG_ 2149416773 P2D_CMD2_DCDCOutputVltg_Set_05 "DCDC输出电压设定";
CM_ SG_ 2149416773 P2D_CMD2_Reserved3_05 "预留3";
CM_ SG_ 2149416773 P2D_CMD2_CommunicationState_05 "PC与DCDC通讯状态";
CM_ SG_ 2149416773 P2D_CMD2_DCDC_Fault_Clear_05 "DCDC故障清除指令";
CM_ SG_ 2149416773 P2D_CMD2_PCSOperationState_05 "PCS运行状态（预留）";
CM_ SG_ 2149416773 P2D_CMD2_DCDCLVoffControl_05 "DCDC低压下电控制";
CM_ SG_ 2149416773 P2D_CMD2_Reserved4_05 "预留4";
CM_ SG_ 2149416774 P2D_CMD2_CRC_06 "预留 （这里没必要做CRC校验吧？）";
CM_ SG_ 2149416774 P2D_CMD2_DCDCSerialNum_06 "预留（原为DCDC编号）";
CM_ SG_ 2149416774 P2D_CMD2_DCDCEnable_06 "使能DCDC命令";
CM_ SG_ 2149416774 P2D_CMD2_Reserved1_06 "预留1";
CM_ SG_ 2149416774 P2D_CMD2_DCDCWrkMdSwtch_06 "DCDC工作状态切换";
CM_ SG_ 2149416774 P2D_CMD2_DCDCWrkMdSet_06 "DCDC工作模式设定";
CM_ SG_ 2149416774 P2D_CMD2_Reserved2_06 "预留2";
CM_ SG_ 2149416774 P2D_CMD2_DCDCOutputCrrntSet_06 "电池电流设定（放正充负）
电池电流=DC低压端电流+DC高压端电流";
CM_ SG_ 2149416774 P2D_CMD2_DCDCOutputVltg_Set_06 "DCDC输出电压设定";
CM_ SG_ 2149416774 P2D_CMD2_Reserved3_06 "预留3";
CM_ SG_ 2149416774 P2D_CMD2_CommunicationState_06 "PC与DCDC通讯状态";
CM_ SG_ 2149416774 P2D_CMD2_DCDC_Fault_Clear_06 "DCDC故障清除指令";
CM_ SG_ 2149416774 P2D_CMD2_PCSOperationState_06 "PCS运行状态（预留）";
CM_ SG_ 2149416774 P2D_CMD2_DCDCLVoffControl_06 "DCDC低压下电控制";
CM_ SG_ 2149416774 P2D_CMD2_Reserved4_06 "预留4";
VAL_ 2332884853 D2M_DCDC_Work_State_53 0 "Standby" 1 "Normal Run" 2 "Bypass" 3 "Fault" ;
VAL_ 2332884853 D2M_DCDC_AlarmSigl_State_53 0 "No alarm" 1 "Alarm occur（告警信号拉低时）" ;
VAL_ 2332884853 D2M_DCDC_LVPower_State_53 0 "Off" 1 "On" ;
VAL_ 2332884853 D2M_DCDC_Enableline_State_53 0 "Disable" 1 "Enable" ;
VAL_ 2332884853 D2M_Communication_State_53 0 "Normal" 1 "CAN lost" ;
VAL_ 2332884853 D2M_DCDC_Sleep_State_53 0 "未休眠" 1 "休眠" ;
VAL_ 2332884854 D2M_DCDC_Work_State_54 0 "Standby" 1 "Normal Run" 2 "Bypass" 3 "Fault" ;
VAL_ 2332884854 D2M_DCDC_AlarmSigl_State_54 0 "No alarm" 1 "Alarm occur（告警信号拉低时）" ;
VAL_ 2332884854 D2M_DCDC_LVPower_State_54 0 "Off" 1 "On" ;
VAL_ 2332884854 D2M_DCDC_Enableline_State_54 0 "Disable" 1 "Enable" ;
VAL_ 2332884854 D2M_Communication_State_54 0 "Normal" 1 "CAN lost" ;
VAL_ 2332884854 D2M_DCDC_Sleep_State_54 0 "未休眠" 1 "休眠" ;
VAL_ 2332884855 D2M_DCDC_Work_State_55 0 "Standby" 1 "Normal Run" 2 "Bypass" 3 "Fault" ;
VAL_ 2332884855 D2M_DCDC_AlarmSigl_State_55 0 "No alarm" 1 "Alarm occur（告警信号拉低时）" ;
VAL_ 2332884855 D2M_DCDC_LVPower_State_55 0 "Off" 1 "On" ;
VAL_ 2332884855 D2M_DCDC_Enableline_State_55 0 "Disable" 1 "Enable" ;
VAL_ 2332884855 D2M_Communication_State_55 0 "Normal" 1 "CAN lost" ;
VAL_ 2332884855 D2M_DCDC_Sleep_State_55 0 "未休眠" 1 "休眠" ;
VAL_ 2332884856 D2M_DCDC_Work_State_56 0 "Standby" 1 "Normal Run" 2 "Bypass" 3 "Fault" ;
VAL_ 2332884856 D2M_DCDC_AlarmSigl_State_56 0 "No alarm" 1 "Alarm occur（告警信号拉低时）" ;
VAL_ 2332884856 D2M_DCDC_LVPower_State_56 0 "Off" 1 "On" ;
VAL_ 2332884856 D2M_DCDC_Enableline_State_56 0 "Disable" 1 "Enable" ;
VAL_ 2332884856 D2M_Communication_State_56 0 "Normal" 1 "CAN lost" ;
VAL_ 2332884856 D2M_DCDC_Sleep_State_56 0 "未休眠" 1 "休眠" ;
VAL_ 2332884857 D2M_DCDC_Work_State_57 0 "Standby" 1 "Normal Run" 2 "Bypass" 3 "Fault" ;
VAL_ 2332884857 D2M_DCDC_AlarmSigl_State_57 0 "No alarm" 1 "Alarm occur（告警信号拉低时）" ;
VAL_ 2332884857 D2M_DCDC_LVPower_State_57 0 "Off" 1 "On" ;
VAL_ 2332884857 D2M_DCDC_Enableline_State_57 0 "Disable" 1 "Enable" ;
VAL_ 2332884857 D2M_Communication_State_57 0 "Normal" 1 "CAN lost" ;
VAL_ 2332884857 D2M_DCDC_Sleep_State_57 0 "未休眠" 1 "休眠" ;
VAL_ 2332884858 D2M_DCDC_Work_State_58 0 "Standby" 1 "Normal Run" 2 "Bypass" 3 "Fault" ;
VAL_ 2332884858 D2M_DCDC_AlarmSigl_State_58 0 "No alarm" 1 "Alarm occur（告警信号拉低时）" ;
VAL_ 2332884858 D2M_DCDC_LVPower_State_58 0 "Off" 1 "On" ;
VAL_ 2332884858 D2M_DCDC_Enableline_State_58 0 "Disable" 1 "Enable" ;
VAL_ 2332884858 D2M_Communication_State_58 0 "Normal" 1 "CAN lost" ;
VAL_ 2332884858 D2M_DCDC_Sleep_State_58 0 "未休眠" 1 "休眠" ;
VAL_ 2332884859 D2M_DCDC_Work_State_59 0 "Standby" 1 "Normal Run" 2 "Bypass" 3 "Fault" ;
VAL_ 2332884859 D2M_DCDC_AlarmSigl_State_59 0 "No alarm" 1 "Alarm occur（告警信号拉低时）" ;
VAL_ 2332884859 D2M_DCDC_LVPower_State_59 0 "Off" 1 "On" ;
VAL_ 2332884859 D2M_DCDC_Enableline_State_59 0 "Disable" 1 "Enable" ;
VAL_ 2332884859 D2M_Communication_State_59 0 "Normal" 1 "CAN lost" ;
VAL_ 2332884859 D2M_DCDC_Sleep_State_59 0 "未休眠" 1 "休眠" ;
VAL_ 2332884860 D2M_DCDC_Work_State_60 0 "Standby" 1 "Normal Run" 2 "Bypass" 3 "Fault" ;
VAL_ 2332884860 D2M_DCDC_AlarmSigl_State_60 0 "No alarm" 1 "Alarm occur（告警信号拉低时）" ;
VAL_ 2332884860 D2M_DCDC_LVPower_State_60 0 "Off" 1 "On" ;
VAL_ 2332884860 D2M_DCDC_Enableline_State_60 0 "Disable" 1 "Enable" ;
VAL_ 2332884860 D2M_Communication_State_60 0 "Normal" 1 "CAN lost" ;
VAL_ 2332884860 D2M_DCDC_Sleep_State_60 0 "未休眠" 1 "休眠" ;
VAL_ 2332884861 D2M_DCDC_Work_State_61 0 "Standby" 1 "Normal Run" 2 "Bypass" 3 "Fault" ;
VAL_ 2332884861 D2M_DCDC_AlarmSigl_State_61 0 "No alarm" 1 "Alarm occur（告警信号拉低时）" ;
VAL_ 2332884861 D2M_DCDC_LVPower_State_61 0 "Off" 1 "On" ;
VAL_ 2332884861 D2M_DCDC_Enableline_State_61 0 "Disable" 1 "Enable" ;
VAL_ 2332884861 D2M_Communication_State_61 0 "Normal" 1 "CAN lost" ;
VAL_ 2332884861 D2M_DCDC_Sleep_State_61 0 "未休眠" 1 "休眠" ;
VAL_ 2332884862 D2M_DCDC_Work_State_62 0 "Standby" 1 "Normal Run" 2 "Bypass" 3 "Fault" ;
VAL_ 2332884862 D2M_DCDC_AlarmSigl_State_62 0 "No alarm" 1 "Alarm occur（告警信号拉低时）" ;
VAL_ 2332884862 D2M_DCDC_LVPower_State_62 0 "Off" 1 "On" ;
VAL_ 2332884862 D2M_DCDC_Enableline_State_62 0 "Disable" 1 "Enable" ;
VAL_ 2332884862 D2M_Communication_State_62 0 "Normal" 1 "CAN lost" ;
VAL_ 2332884862 D2M_DCDC_Sleep_State_62 0 "未休眠" 1 "休眠" ;
VAL_ 2332884863 D2M_DCDC_Work_State_63 0 "Standby" 1 "Normal Run" 2 "Bypass" 3 "Fault" ;
VAL_ 2332884863 D2M_DCDC_AlarmSigl_State_63 0 "No alarm" 1 "Alarm occur（告警信号拉低时）" ;
VAL_ 2332884863 D2M_DCDC_LVPower_State_63 0 "Off" 1 "On" ;
VAL_ 2332884863 D2M_DCDC_Enableline_State_63 0 "Disable" 1 "Enable" ;
VAL_ 2332884863 D2M_Communication_State_63 0 "Normal" 1 "CAN lost" ;
VAL_ 2332884863 D2M_DCDC_Sleep_State_63 0 "未休眠" 1 "休眠" ;
VAL_ 2333081409 D2M_DCDC_FaultClass_01 0 "无故障" 1 "一级故障" 2 "二级故障" 3 "三级故障" 4 "四级故障" 5 "五级故障" 6 "六级故障" 7 "七级故障" ;
VAL_ 2333081410 D2M_DCDC_FaultClass_02 0 "无故障" 1 "一级故障" 2 "二级故障" 3 "三级故障" 4 "四级故障" 5 "五级故障" 6 "六级故障" 7 "七级故障" ;
VAL_ 2333081411 D2M_DCDC_FaultClass_03 0 "无故障" 1 "一级故障" 2 "二级故障" 3 "三级故障" 4 "四级故障" 5 "五级故障" 6 "六级故障" 7 "七级故障" ;
VAL_ 2333081412 D2M_DCDC_FaultClass_04 0 "无故障" 1 "一级故障" 2 "二级故障" 3 "三级故障" 4 "四级故障" 5 "五级故障" 6 "六级故障" 7 "七级故障" ;
VAL_ 2333081413 D2M_DCDC_FaultClass_05 0 "无故障" 1 "一级故障" 2 "二级故障" 3 "三级故障" 4 "四级故障" 5 "五级故障" 6 "六级故障" 7 "七级故障" ;
VAL_ 2333081414 D2M_DCDC_FaultClass_06 0 "无故障" 1 "一级故障" 2 "二级故障" 3 "三级故障" 4 "四级故障" 5 "五级故障" 6 "六级故障" 7 "七级故障" ;
VAL_ 2333081415 D2M_DCDC_FaultClass_07 0 "无故障" 1 "一级故障" 2 "二级故障" 3 "三级故障" 4 "四级故障" 5 "五级故障" 6 "六级故障" 7 "七级故障" ;
VAL_ 2333081416 D2M_DCDC_FaultClass_08 0 "无故障" 1 "一级故障" 2 "二级故障" 3 "三级故障" 4 "四级故障" 5 "五级故障" 6 "六级故障" 7 "七级故障" ;
VAL_ 2333081417 D2M_DCDC_FaultClass_09 0 "无故障" 1 "一级故障" 2 "二级故障" 3 "三级故障" 4 "四级故障" 5 "五级故障" 6 "六级故障" 7 "七级故障" ;
VAL_ 2333081418 D2M_DCDC_FaultClass_10 0 "无故障" 1 "一级故障" 2 "二级故障" 3 "三级故障" 4 "四级故障" 5 "五级故障" 6 "六级故障" 7 "七级故障" ;
VAL_ 2333081419 D2M_DCDC_FaultClass_11 0 "无故障" 1 "一级故障" 2 "二级故障" 3 "三级故障" 4 "四级故障" 5 "五级故障" 6 "六级故障" 7 "七级故障" ;
VAL_ 2333081420 D2M_DCDC_FaultClass_12 0 "无故障" 1 "一级故障" 2 "二级故障" 3 "三级故障" 4 "四级故障" 5 "五级故障" 6 "六级故障" 7 "七级故障" ;
VAL_ 2333081421 D2M_DCDC_FaultClass_13 0 "无故障" 1 "一级故障" 2 "二级故障" 3 "三级故障" 4 "四级故障" 5 "五级故障" 6 "六级故障" 7 "七级故障" ;
VAL_ 2333081422 D2M_DCDC_FaultClass_14 0 "无故障" 1 "一级故障" 2 "二级故障" 3 "三级故障" 4 "四级故障" 5 "五级故障" 6 "六级故障" 7 "七级故障" ;
VAL_ 2333081423 D2M_DCDC_FaultClass_15 0 "无故障" 1 "一级故障" 2 "二级故障" 3 "三级故障" 4 "四级故障" 5 "五级故障" 6 "六级故障" 7 "七级故障" ;
VAL_ 2333081424 D2M_DCDC_FaultClass_16 0 "无故障" 1 "一级故障" 2 "二级故障" 3 "三级故障" 4 "四级故障" 5 "五级故障" 6 "六级故障" 7 "七级故障" ;
VAL_ 2333081425 D2M_DCDC_FaultClass_17 0 "无故障" 1 "一级故障" 2 "二级故障" 3 "三级故障" 4 "四级故障" 5 "五级故障" 6 "六级故障" 7 "七级故障" ;
VAL_ 2333081426 D2M_DCDC_FaultClass_18 0 "无故障" 1 "一级故障" 2 "二级故障" 3 "三级故障" 4 "四级故障" 5 "五级故障" 6 "六级故障" 7 "七级故障" ;
VAL_ 2333081427 D2M_DCDC_FaultClass_19 0 "无故障" 1 "一级故障" 2 "二级故障" 3 "三级故障" 4 "四级故障" 5 "五级故障" 6 "六级故障" 7 "七级故障" ;
VAL_ 2333081428 D2M_DCDC_FaultClass_20 0 "无故障" 1 "一级故障" 2 "二级故障" 3 "三级故障" 4 "四级故障" 5 "五级故障" 6 "六级故障" 7 "七级故障" ;
VAL_ 2333081429 D2M_DCDC_FaultClass_21 0 "无故障" 1 "一级故障" 2 "二级故障" 3 "三级故障" 4 "四级故障" 5 "五级故障" 6 "六级故障" 7 "七级故障" ;
VAL_ 2333081430 D2M_DCDC_FaultClass_22 0 "无故障" 1 "一级故障" 2 "二级故障" 3 "三级故障" 4 "四级故障" 5 "五级故障" 6 "六级故障" 7 "七级故障" ;
VAL_ 2333081431 D2M_DCDC_FaultClass_23 0 "无故障" 1 "一级故障" 2 "二级故障" 3 "三级故障" 4 "四级故障" 5 "五级故障" 6 "六级故障" 7 "七级故障" ;
VAL_ 2333081432 D2M_DCDC_FaultClass_24 0 "无故障" 1 "一级故障" 2 "二级故障" 3 "三级故障" 4 "四级故障" 5 "五级故障" 6 "六级故障" 7 "七级故障" ;
VAL_ 2333081433 D2M_DCDC_FaultClass_25 0 "无故障" 1 "一级故障" 2 "二级故障" 3 "三级故障" 4 "四级故障" 5 "五级故障" 6 "六级故障" 7 "七级故障" ;
VAL_ 2333081434 D2M_DCDC_FaultClass_26 0 "无故障" 1 "一级故障" 2 "二级故障" 3 "三级故障" 4 "四级故障" 5 "五级故障" 6 "六级故障" 7 "七级故障" ;
VAL_ 2333081435 D2M_DCDC_FaultClass_27 0 "无故障" 1 "一级故障" 2 "二级故障" 3 "三级故障" 4 "四级故障" 5 "五级故障" 6 "六级故障" 7 "七级故障" ;
VAL_ 2333081436 D2M_DCDC_FaultClass_28 0 "无故障" 1 "一级故障" 2 "二级故障" 3 "三级故障" 4 "四级故障" 5 "五级故障" 6 "六级故障" 7 "七级故障" ;
VAL_ 2333081437 D2M_DCDC_FaultClass_29 0 "无故障" 1 "一级故障" 2 "二级故障" 3 "三级故障" 4 "四级故障" 5 "五级故障" 6 "六级故障" 7 "七级故障" ;
VAL_ 2333081438 D2M_DCDC_FaultClass_30 0 "无故障" 1 "一级故障" 2 "二级故障" 3 "三级故障" 4 "四级故障" 5 "五级故障" 6 "六级故障" 7 "七级故障" ;
VAL_ 2333081439 D2M_DCDC_FaultClass_31 0 "无故障" 1 "一级故障" 2 "二级故障" 3 "三级故障" 4 "四级故障" 5 "五级故障" 6 "六级故障" 7 "七级故障" ;
VAL_ 2333081440 D2M_DCDC_FaultClass_32 0 "无故障" 1 "一级故障" 2 "二级故障" 3 "三级故障" 4 "四级故障" 5 "五级故障" 6 "六级故障" 7 "七级故障" ;
VAL_ 2333081441 D2M_DCDC_FaultClass_33 0 "无故障" 1 "一级故障" 2 "二级故障" 3 "三级故障" 4 "四级故障" 5 "五级故障" 6 "六级故障" 7 "七级故障" ;
VAL_ 2333081442 D2M_DCDC_FaultClass_34 0 "无故障" 1 "一级故障" 2 "二级故障" 3 "三级故障" 4 "四级故障" 5 "五级故障" 6 "六级故障" 7 "七级故障" ;
VAL_ 2333081443 D2M_DCDC_FaultClass_35 0 "无故障" 1 "一级故障" 2 "二级故障" 3 "三级故障" 4 "四级故障" 5 "五级故障" 6 "六级故障" 7 "七级故障" ;
VAL_ 2333081444 D2M_DCDC_FaultClass_36 0 "无故障" 1 "一级故障" 2 "二级故障" 3 "三级故障" 4 "四级故障" 5 "五级故障" 6 "六级故障" 7 "七级故障" ;
VAL_ 2333081445 D2M_DCDC_FaultClass_37 0 "无故障" 1 "一级故障" 2 "二级故障" 3 "三级故障" 4 "四级故障" 5 "五级故障" 6 "六级故障" 7 "七级故障" ;
VAL_ 2333081446 D2M_DCDC_FaultClass_38 0 "无故障" 1 "一级故障" 2 "二级故障" 3 "三级故障" 4 "四级故障" 5 "五级故障" 6 "六级故障" 7 "七级故障" ;
VAL_ 2333081447 D2M_DCDC_FaultClass_39 0 "无故障" 1 "一级故障" 2 "二级故障" 3 "三级故障" 4 "四级故障" 5 "五级故障" 6 "六级故障" 7 "七级故障" ;
VAL_ 2333081448 D2M_DCDC_FaultClass_40 0 "无故障" 1 "一级故障" 2 "二级故障" 3 "三级故障" 4 "四级故障" 5 "五级故障" 6 "六级故障" 7 "七级故障" ;
VAL_ 2333081449 D2M_DCDC_FaultClass_41 0 "无故障" 1 "一级故障" 2 "二级故障" 3 "三级故障" 4 "四级故障" 5 "五级故障" 6 "六级故障" 7 "七级故障" ;
VAL_ 2333081450 D2M_DCDC_FaultClass_42 0 "无故障" 1 "一级故障" 2 "二级故障" 3 "三级故障" 4 "四级故障" 5 "五级故障" 6 "六级故障" 7 "七级故障" ;
VAL_ 2333081451 D2M_DCDC_FaultClass_43 0 "无故障" 1 "一级故障" 2 "二级故障" 3 "三级故障" 4 "四级故障" 5 "五级故障" 6 "六级故障" 7 "七级故障" ;
VAL_ 2333081452 D2M_DCDC_FaultClass_44 0 "无故障" 1 "一级故障" 2 "二级故障" 3 "三级故障" 4 "四级故障" 5 "五级故障" 6 "六级故障" 7 "七级故障" ;
VAL_ 2333081453 D2M_DCDC_FaultClass_45 0 "无故障" 1 "一级故障" 2 "二级故障" 3 "三级故障" 4 "四级故障" 5 "五级故障" 6 "六级故障" 7 "七级故障" ;
VAL_ 2333081454 D2M_DCDC_FaultClass_46 0 "无故障" 1 "一级故障" 2 "二级故障" 3 "三级故障" 4 "四级故障" 5 "五级故障" 6 "六级故障" 7 "七级故障" ;
VAL_ 2333081455 D2M_DCDC_FaultClass_47 0 "无故障" 1 "一级故障" 2 "二级故障" 3 "三级故障" 4 "四级故障" 5 "五级故障" 6 "六级故障" 7 "七级故障" ;
VAL_ 2333081456 D2M_DCDC_FaultClass_48 0 "无故障" 1 "一级故障" 2 "二级故障" 3 "三级故障" 4 "四级故障" 5 "五级故障" 6 "六级故障" 7 "七级故障" ;
VAL_ 2333081457 D2M_DCDC_FaultClass_49 0 "无故障" 1 "一级故障" 2 "二级故障" 3 "三级故障" 4 "四级故障" 5 "五级故障" 6 "六级故障" 7 "七级故障" ;
VAL_ 2333081458 D2M_DCDC_FaultClass_50 0 "无故障" 1 "一级故障" 2 "二级故障" 3 "三级故障" 4 "四级故障" 5 "五级故障" 6 "六级故障" 7 "七级故障" ;
VAL_ 2333081459 D2M_DCDC_FaultClass_51 0 "无故障" 1 "一级故障" 2 "二级故障" 3 "三级故障" 4 "四级故障" 5 "五级故障" 6 "六级故障" 7 "七级故障" ;
VAL_ 2333081460 D2M_DCDC_FaultClass_52 0 "无故障" 1 "一级故障" 2 "二级故障" 3 "三级故障" 4 "四级故障" 5 "五级故障" 6 "六级故障" 7 "七级故障" ;
VAL_ 2333081461 D2M_DCDC_FaultClass_53 0 "无故障" 1 "一级故障" 2 "二级故障" 3 "三级故障" 4 "四级故障" 5 "五级故障" 6 "六级故障" 7 "七级故障" ;
VAL_ 2333081462 D2M_DCDC_FaultClass_54 0 "无故障" 1 "一级故障" 2 "二级故障" 3 "三级故障" 4 "四级故障" 5 "五级故障" 6 "六级故障" 7 "七级故障" ;
VAL_ 2333081463 D2M_DCDC_FaultClass_55 0 "无故障" 1 "一级故障" 2 "二级故障" 3 "三级故障" 4 "四级故障" 5 "五级故障" 6 "六级故障" 7 "七级故障" ;
VAL_ 2333081464 D2M_DCDC_FaultClass_56 0 "无故障" 1 "一级故障" 2 "二级故障" 3 "三级故障" 4 "四级故障" 5 "五级故障" 6 "六级故障" 7 "七级故障" ;
VAL_ 2333081465 D2M_DCDC_FaultClass_57 0 "无故障" 1 "一级故障" 2 "二级故障" 3 "三级故障" 4 "四级故障" 5 "五级故障" 6 "六级故障" 7 "七级故障" ;
VAL_ 2333081466 D2M_DCDC_FaultClass_58 0 "无故障" 1 "一级故障" 2 "二级故障" 3 "三级故障" 4 "四级故障" 5 "五级故障" 6 "六级故障" 7 "七级故障" ;
VAL_ 2333081467 D2M_DCDC_FaultClass_59 0 "无故障" 1 "一级故障" 2 "二级故障" 3 "三级故障" 4 "四级故障" 5 "五级故障" 6 "六级故障" 7 "七级故障" ;
VAL_ 2333081468 D2M_DCDC_FaultClass_60 0 "无故障" 1 "一级故障" 2 "二级故障" 3 "三级故障" 4 "四级故障" 5 "五级故障" 6 "六级故障" 7 "七级故障" ;
VAL_ 2333081469 D2M_DCDC_FaultClass_61 0 "无故障" 1 "一级故障" 2 "二级故障" 3 "三级故障" 4 "四级故障" 5 "五级故障" 6 "六级故障" 7 "七级故障" ;
VAL_ 2333081470 D2M_DCDC_FaultClass_62 0 "无故障" 1 "一级故障" 2 "二级故障" 3 "三级故障" 4 "四级故障" 5 "五级故障" 6 "六级故障" 7 "七级故障" ;
VAL_ 2333081471 D2M_DCDC_FaultClass_63 0 "无故障" 1 "一级故障" 2 "二级故障" 3 "三级故障" 4 "四级故障" 5 "五级故障" 6 "六级故障" 7 "七级故障" ;
VAL_ 2149416769 P2D_CMD2_DCDCEnable_01 0 "Disable" 1 "Enable" ;
VAL_ 2149416769 P2D_CMD2_DCDCWrkMdSwtch_01 0 "Standby" 1 "Normal Run" 2 "Bypass" 3 "Reserved" ;
VAL_ 2149416769 P2D_CMD2_DCDCWrkMdSet_01 0 "Constant Vlotage" 1 "Constant Current" 2 "Steady Current(not greater than)" 3 "Steady Current(not less than)" ;
VAL_ 2149416769 P2D_CMD2_CommunicationState_01 0 "Normal" 1 "CAN lost" ;
VAL_ 2149416769 P2D_CMD2_DCDC_Fault_Clear_01 0 "Not Clear" 1 "Clear" ;
VAL_ 2149416769 P2D_CMD2_PCSOperationState_01 0 "Standby" 1 "Discharge" 2 "Charge" 3 "Fault" ;
VAL_ 2149416769 P2D_CMD2_DCDCLVoffControl_01 0 "不允许低压下电" 1 "允许低压下电" ;
VAL_ 2149416770 P2D_CMD2_DCDCEnable_02 0 "Disable" 1 "Enable" ;
VAL_ 2149416770 P2D_CMD2_DCDCWrkMdSwtch_02 0 "Standby" 1 "Normal Run" 2 "Bypass" 3 "Reserved" ;
VAL_ 2149416770 P2D_CMD2_DCDCWrkMdSet_02 0 "Constant Vlotage" 1 "Constant Current" 2 "Steady Current(not greater than)" 3 "Steady Current(not less than)" ;
VAL_ 2149416770 P2D_CMD2_CommunicationState_02 0 "Normal" 1 "CAN lost" ;
VAL_ 2149416770 P2D_CMD2_DCDC_Fault_Clear_02 0 "Not Clear" 1 "Clear" ;
VAL_ 2149416770 P2D_CMD2_PCSOperationState_02 0 "Standby" 1 "Discharge" 2 "Charge" 3 "Fault" ;
VAL_ 2149416770 P2D_CMD2_DCDCLVoffControl_02 0 "不允许低压下电" 1 "允许低压下电" ;
VAL_ 2149416771 P2D_CMD2_DCDCEnable_03 0 "Disable" 1 "Enable" ;
VAL_ 2149416771 P2D_CMD2_DCDCWrkMdSwtch_03 0 "Standby" 1 "Normal Run" 2 "Bypass" 3 "Reserved" ;
VAL_ 2149416771 P2D_CMD2_DCDCWrkMdSet_03 0 "Constant Vlotage" 1 "Constant Current" 2 "Steady Current(not greater than)" 3 "Steady Current(not less than)" ;
VAL_ 2149416771 P2D_CMD2_CommunicationState_03 0 "Normal" 1 "CAN lost" ;
VAL_ 2149416771 P2D_CMD2_DCDC_Fault_Clear_03 0 "Not Clear" 1 "Clear" ;
VAL_ 2149416771 P2D_CMD2_PCSOperationState_03 0 "Standby" 1 "Discharge" 2 "Charge" 3 "Fault" ;
VAL_ 2149416771 P2D_CMD2_DCDCLVoffControl_03 0 "不允许低压下电" 1 "允许低压下电" ;
VAL_ 2149416772 P2D_CMD2_DCDCEnable_04 0 "Disable" 1 "Enable" ;
VAL_ 2149416772 P2D_CMD2_DCDCWrkMdSwtch_04 0 "Standby" 1 "Normal Run" 2 "Bypass" 3 "Reserved" ;
VAL_ 2149416772 P2D_CMD2_DCDCWrkMdSet_04 0 "Constant Vlotage" 1 "Constant Current" 2 "Steady Current(not greater than)" 3 "Steady Current(not less than)" ;
VAL_ 2149416772 P2D_CMD2_CommunicationState_04 0 "Normal" 1 "CAN lost" ;
VAL_ 2149416772 P2D_CMD2_DCDC_Fault_Clear_04 0 "Not Clear" 1 "Clear" ;
VAL_ 2149416772 P2D_CMD2_PCSOperationState_04 0 "Standby" 1 "Discharge" 2 "Charge" 3 "Fault" ;
VAL_ 2149416772 P2D_CMD2_DCDCLVoffControl_04 0 "不允许低压下电" 1 "允许低压下电" ;
VAL_ 2149416773 P2D_CMD2_DCDCEnable_05 0 "Disable" 1 "Enable" ;
VAL_ 2149416773 P2D_CMD2_DCDCWrkMdSwtch_05 0 "Standby" 1 "Normal Run" 2 "Bypass" 3 "Reserved" ;
VAL_ 2149416773 P2D_CMD2_DCDCWrkMdSet_05 0 "Constant Vlotage" 1 "Constant Current" 2 "Steady Current(not greater than)" 3 "Steady Current(not less than)" ;
VAL_ 2149416773 P2D_CMD2_CommunicationState_05 0 "Normal" 1 "CAN lost" ;
VAL_ 2149416773 P2D_CMD2_DCDC_Fault_Clear_05 0 "Not Clear" 1 "Clear" ;
VAL_ 2149416773 P2D_CMD2_PCSOperationState_05 0 "Standby" 1 "Discharge" 2 "Charge" 3 "Fault" ;
VAL_ 2149416773 P2D_CMD2_DCDCLVoffControl_05 0 "不允许低压下电" 1 "允许低压下电" ;
VAL_ 2149416774 P2D_CMD2_DCDCEnable_06 0 "Disable" 1 "Enable" ;
VAL_ 2149416774 P2D_CMD2_DCDCWrkMdSwtch_06 0 "Standby" 1 "Normal Run" 2 "Bypass" 3 "Reserved" ;
VAL_ 2149416774 P2D_CMD2_DCDCWrkMdSet_06 0 "Constant Vlotage" 1 "Constant Current" 2 "Steady Current(not greater than)" 3 "Steady Current(not less than)" ;
VAL_ 2149416774 P2D_CMD2_CommunicationState_06 0 "Normal" 1 "CAN lost" ;
VAL_ 2149416774 P2D_CMD2_DCDC_Fault_Clear_06 0 "Not Clear" 1 "Clear" ;
VAL_ 2149416774 P2D_CMD2_PCSOperationState_06 0 "Standby" 1 "Discharge" 2 "Charge" 3 "Fault" ;
VAL_ 2149416774 P2D_CMD2_DCDCLVoffControl_06 0 "不允许低压下电" 1 "允许低压下电" ;
VERSION ""

NS_ :

BS_:

BU_: MBMU PC SBMU IMM ETH DCDC LEMS

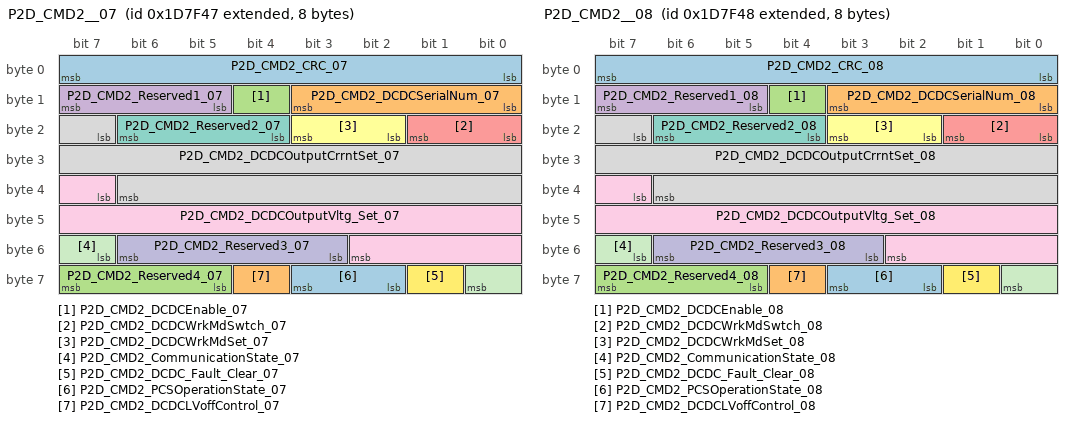
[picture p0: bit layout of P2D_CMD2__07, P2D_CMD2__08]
BO_ 2149416775 P2D_CMD2__07: 8 PC
 SG_ P2D_CMD2_CRC_07 : 0|8@1+ (1,0) [0|255] ""  DCDC
 SG_ P2D_CMD2_DCDCSerialNum_07 : 8|4@1+ (1,0) [0|15] ""  DCDC
 SG_ P2D_CMD2_DCDCEnable_07 : 12|1@1+ (1,0) [0|1] ""  DCDC
 SG_ P2D_CMD2_Reserved1_07 : 13|3@1+ (1,0) [0|7] ""  DCDC
 SG_ P2D_CMD2_DCDCWrkMdSwtch_07 : 16|2@1+ (1,0) [0|3] ""  DCDC
 SG_ P2D_CMD2_DCDCWrkMdSet_07 : 18|2@1+ (1,0) [0|3] ""  DCDC
 SG_ P2D_CMD2_Reserved2_07 : 20|3@1+ (1,0) [0|7] ""  DCDC
 SG_ P2D_CMD2_DCDCOutputCrrntSet_07 : 23|16@1+ (0.05,-2000) [-2000|1276.75] "A"  DCDC
 SG_ P2D_CMD2_DCDCOutputVltg_Set_07 : 39|12@1+ (0.1,-200) [-200|209.5] "V"  DCDC
 SG_ P2D_CMD2_Reserved3_07 : 51|4@1+ (1,0) [0|15] ""  DCDC
 SG_ P2D_CMD2_CommunicationState_07 : 55|2@1+ (1,0) [0|3] ""  DCDC
 SG_ P2D_CMD2_DCDC_Fault_Clear_07 : 57|1@1+ (1,0) [0|1] ""  DCDC
 SG_ P2D_CMD2_PCSOperationState_07 : 58|2@1+ (1,0) [0|3] ""  DCDC
 SG_ P2D_CMD2_DCDCLVoffControl_07 : 60|1@1+ (1,0) [0|1] ""  DCDC
 SG_ P2D_CMD2_Reserved4_07 : 61|3@1+ (1,0) [0|7] ""  DCDC

BO_ 2149416776 P2D_CMD2__08: 8 PC
 SG_ P2D_CMD2_CRC_08 : 0|8@1+ (1,0) [0|255] ""  DCDC
 SG_ P2D_CMD2_DCDCSerialNum_08 : 8|4@1+ (1,0) [0|15] ""  DCDC
 SG_ P2D_CMD2_DCDCEnable_08 : 12|1@1+ (1,0) [0|1] ""  DCDC
 SG_ P2D_CMD2_Reserved1_08 : 13|3@1+ (1,0) [0|7] ""  DCDC
 SG_ P2D_CMD2_DCDCWrkMdSwtch_08 : 16|2@1+ (1,0) [0|3] ""  DCDC
 SG_ P2D_CMD2_DCDCWrkMdSet_08 : 18|2@1+ (1,0) [0|3] ""  DCDC
 SG_ P2D_CMD2_Reserved2_08 : 20|3@1+ (1,0) [0|7] ""  DCDC
 SG_ P2D_CMD2_DCDCOutputCrrntSet_08 : 23|16@1+ (0.05,-2000) [-2000|1276.75] "A"  DCDC
 SG_ P2D_CMD2_DCDCOutputVltg_Set_08 : 39|12@1+ (0.1,-200) [-200|209.5] "V"  DCDC
 SG_ P2D_CMD2_Reserved3_08 : 51|4@1+ (1,0) [0|15] ""  DCDC
 SG_ P2D_CMD2_CommunicationState_08 : 55|2@1+ (1,0) [0|3] ""  DCDC
 SG_ P2D_CMD2_DCDC_Fault_Clear_08 : 57|1@1+ (1,0) [0|1] ""  DCDC
 SG_ P2D_CMD2_PCSOperationState_08 : 58|2@1+ (1,0) [0|3] ""  DCDC
 SG_ P2D_CMD2_DCDCLVoffControl_08 : 60|1@1+ (1,0) [0|1] ""  DCDC
 SG_ P2D_CMD2_Reserved4_08 : 61|3@1+ (1,0) [0|7] ""  DCDC

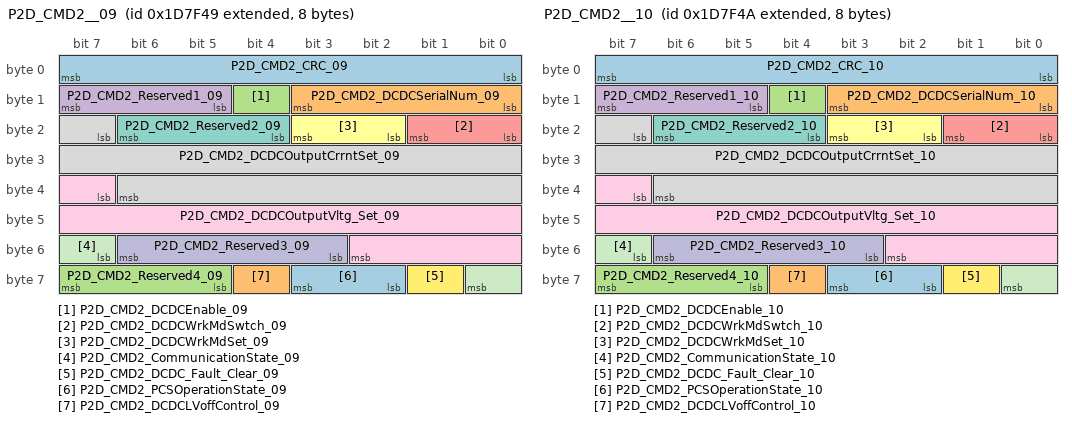
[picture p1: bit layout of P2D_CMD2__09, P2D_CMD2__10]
BO_ 2149416777 P2D_CMD2__09: 8 PC
 SG_ P2D_CMD2_CRC_09 : 0|8@1+ (1,0) [0|255] ""  DCDC
 SG_ P2D_CMD2_DCDCSerialNum_09 : 8|4@1+ (1,0) [0|15] ""  DCDC
 SG_ P2D_CMD2_DCDCEnable_09 : 12|1@1+ (1,0) [0|1] ""  DCDC
 SG_ P2D_CMD2_Reserved1_09 : 13|3@1+ (1,0) [0|7] ""  DCDC
 SG_ P2D_CMD2_DCDCWrkMdSwtch_09 : 16|2@1+ (1,0) [0|3] ""  DCDC
 SG_ P2D_CMD2_DCDCWrkMdSet_09 : 18|2@1+ (1,0) [0|3] ""  DCDC
 SG_ P2D_CMD2_Reserved2_09 : 20|3@1+ (1,0) [0|7] ""  DCDC
 SG_ P2D_CMD2_DCDCOutputCrrntSet_09 : 23|16@1+ (0.05,-2000) [-2000|1276.75] "A"  DCDC
 SG_ P2D_CMD2_DCDCOutputVltg_Set_09 : 39|12@1+ (0.1,-200) [-200|209.5] "V"  DCDC
 SG_ P2D_CMD2_Reserved3_09 : 51|4@1+ (1,0) [0|15] ""  DCDC
 SG_ P2D_CMD2_CommunicationState_09 : 55|2@1+ (1,0) [0|3] ""  DCDC
 SG_ P2D_CMD2_DCDC_Fault_Clear_09 : 57|1@1+ (1,0) [0|1] ""  DCDC
 SG_ P2D_CMD2_PCSOperationState_09 : 58|2@1+ (1,0) [0|3] ""  DCDC
 SG_ P2D_CMD2_DCDCLVoffControl_09 : 60|1@1+ (1,0) [0|1] ""  DCDC
 SG_ P2D_CMD2_Reserved4_09 : 61|3@1+ (1,0) [0|7] ""  DCDC

BO_ 2149416778 P2D_CMD2__10: 8 PC
 SG_ P2D_CMD2_CRC_10 : 0|8@1+ (1,0) [0|255] ""  DCDC
 SG_ P2D_CMD2_DCDCSerialNum_10 : 8|4@1+ (1,0) [0|15] ""  DCDC
 SG_ P2D_CMD2_DCDCEnable_10 : 12|1@1+ (1,0) [0|1] ""  DCDC
 SG_ P2D_CMD2_Reserved1_10 : 13|3@1+ (1,0) [0|7] ""  DCDC
 SG_ P2D_CMD2_DCDCWrkMdSwtch_10 : 16|2@1+ (1,0) [0|3] ""  DCDC
 SG_ P2D_CMD2_DCDCWrkMdSet_10 : 18|2@1+ (1,0) [0|3] ""  DCDC
 SG_ P2D_CMD2_Reserved2_10 : 20|3@1+ (1,0) [0|7] ""  DCDC
 SG_ P2D_CMD2_DCDCOutputCrrntSet_10 : 23|16@1+ (0.05,-2000) [-2000|1276.75] "A"  DCDC
 SG_ P2D_CMD2_DCDCOutputVltg_Set_10 : 39|12@1+ (0.1,-200) [-200|209.5] "V"  DCDC
 SG_ P2D_CMD2_Reserved3_10 : 51|4@1+ (1,0) [0|15] ""  DCDC
 SG_ P2D_CMD2_CommunicationState_10 : 55|2@1+ (1,0) [0|3] ""  DCDC
 SG_ P2D_CMD2_DCDC_Fault_Clear_10 : 57|1@1+ (1,0) [0|1] ""  DCDC
 SG_ P2D_CMD2_PCSOperationState_10 : 58|2@1+ (1,0) [0|3] ""  DCDC
 SG_ P2D_CMD2_DCDCLVoffControl_10 : 60|1@1+ (1,0) [0|1] ""  DCDC
 SG_ P2D_CMD2_Reserved4_10 : 61|3@1+ (1,0) [0|7] ""  DCDC

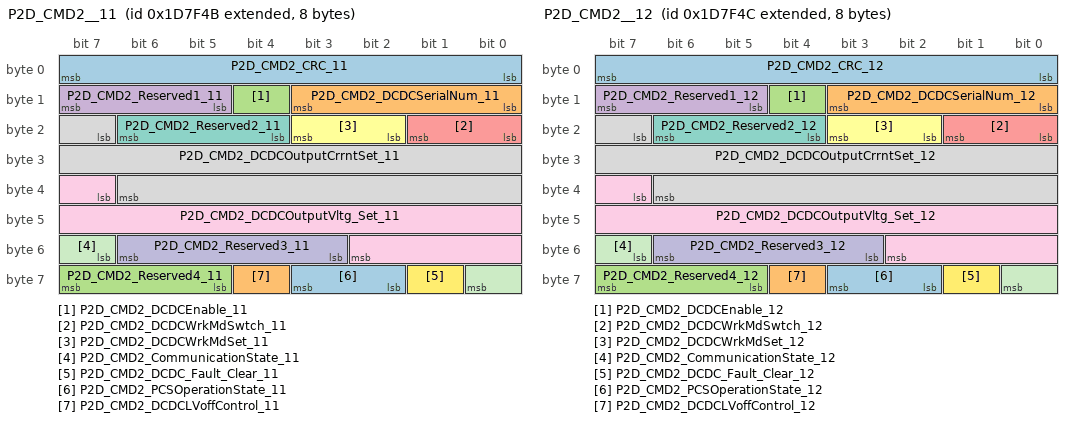
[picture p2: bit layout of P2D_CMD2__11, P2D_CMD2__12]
BO_ 2149416779 P2D_CMD2__11: 8 PC
 SG_ P2D_CMD2_CRC_11 : 0|8@1+ (1,0) [0|255] ""  DCDC
 SG_ P2D_CMD2_DCDCSerialNum_11 : 8|4@1+ (1,0) [0|15] ""  DCDC
 SG_ P2D_CMD2_DCDCEnable_11 : 12|1@1+ (1,0) [0|1] ""  DCDC
 SG_ P2D_CMD2_Reserved1_11 : 13|3@1+ (1,0) [0|7] ""  DCDC
 SG_ P2D_CMD2_DCDCWrkMdSwtch_11 : 16|2@1+ (1,0) [0|3] ""  DCDC
 SG_ P2D_CMD2_DCDCWrkMdSet_11 : 18|2@1+ (1,0) [0|3] ""  DCDC
 SG_ P2D_CMD2_Reserved2_11 : 20|3@1+ (1,0) [0|7] ""  DCDC
 SG_ P2D_CMD2_DCDCOutputCrrntSet_11 : 23|16@1+ (0.05,-2000) [-2000|1276.75] "A"  DCDC
 SG_ P2D_CMD2_DCDCOutputVltg_Set_11 : 39|12@1+ (0.1,-200) [-200|209.5] "V"  DCDC
 SG_ P2D_CMD2_Reserved3_11 : 51|4@1+ (1,0) [0|15] ""  DCDC
 SG_ P2D_CMD2_CommunicationState_11 : 55|2@1+ (1,0) [0|3] ""  DCDC
 SG_ P2D_CMD2_DCDC_Fault_Clear_11 : 57|1@1+ (1,0) [0|1] ""  DCDC
 SG_ P2D_CMD2_PCSOperationState_11 : 58|2@1+ (1,0) [0|3] ""  DCDC
 SG_ P2D_CMD2_DCDCLVoffControl_11 : 60|1@1+ (1,0) [0|1] ""  DCDC
 SG_ P2D_CMD2_Reserved4_11 : 61|3@1+ (1,0) [0|7] ""  DCDC

BO_ 2149416780 P2D_CMD2__12: 8 PC
 SG_ P2D_CMD2_CRC_12 : 0|8@1+ (1,0) [0|255] ""  DCDC
 SG_ P2D_CMD2_DCDCSerialNum_12 : 8|4@1+ (1,0) [0|15] ""  DCDC
 SG_ P2D_CMD2_DCDCEnable_12 : 12|1@1+ (1,0) [0|1] ""  DCDC
 SG_ P2D_CMD2_Reserved1_12 : 13|3@1+ (1,0) [0|7] ""  DCDC
 SG_ P2D_CMD2_DCDCWrkMdSwtch_12 : 16|2@1+ (1,0) [0|3] ""  DCDC
 SG_ P2D_CMD2_DCDCWrkMdSet_12 : 18|2@1+ (1,0) [0|3] ""  DCDC
 SG_ P2D_CMD2_Reserved2_12 : 20|3@1+ (1,0) [0|7] ""  DCDC
 SG_ P2D_CMD2_DCDCOutputCrrntSet_12 : 23|16@1+ (0.05,-2000) [-2000|1276.75] "A"  DCDC
 SG_ P2D_CMD2_DCDCOutputVltg_Set_12 : 39|12@1+ (0.1,-200) [-200|209.5] "V"  DCDC
 SG_ P2D_CMD2_Reserved3_12 : 51|4@1+ (1,0) [0|15] ""  DCDC
 SG_ P2D_CMD2_CommunicationState_12 : 55|2@1+ (1,0) [0|3] ""  DCDC
 SG_ P2D_CMD2_DCDC_Fault_Clear_12 : 57|1@1+ (1,0) [0|1] ""  DCDC
 SG_ P2D_CMD2_PCSOperationState_12 : 58|2@1+ (1,0) [0|3] ""  DCDC
 SG_ P2D_CMD2_DCDCLVoffControl_12 : 60|1@1+ (1,0) [0|1] ""  DCDC
 SG_ P2D_CMD2_Reserved4_12 : 61|3@1+ (1,0) [0|7] ""  DCDC

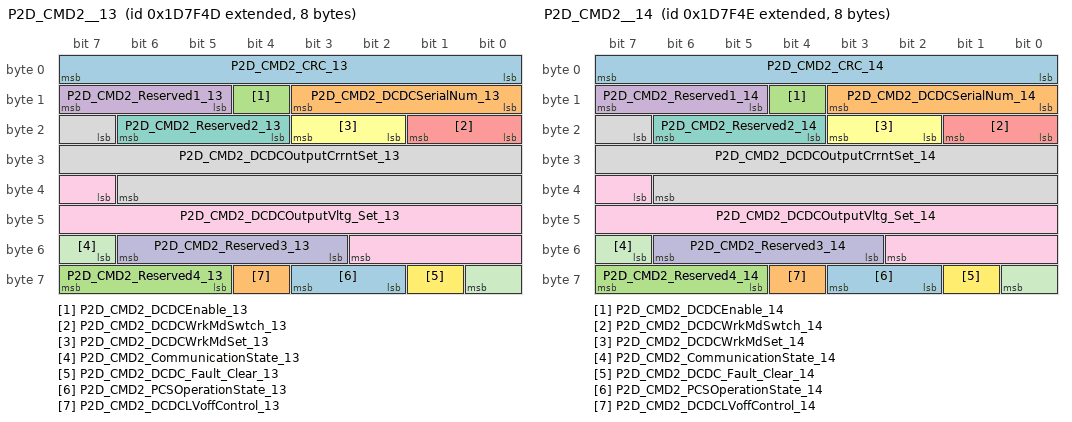
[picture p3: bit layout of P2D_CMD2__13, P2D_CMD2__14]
BO_ 2149416781 P2D_CMD2__13: 8 PC
 SG_ P2D_CMD2_CRC_13 : 0|8@1+ (1,0) [0|255] ""  DCDC
 SG_ P2D_CMD2_DCDCSerialNum_13 : 8|4@1+ (1,0) [0|15] ""  DCDC
 SG_ P2D_CMD2_DCDCEnable_13 : 12|1@1+ (1,0) [0|1] ""  DCDC
 SG_ P2D_CMD2_Reserved1_13 : 13|3@1+ (1,0) [0|7] ""  DCDC
 SG_ P2D_CMD2_DCDCWrkMdSwtch_13 : 16|2@1+ (1,0) [0|3] ""  DCDC
 SG_ P2D_CMD2_DCDCWrkMdSet_13 : 18|2@1+ (1,0) [0|3] ""  DCDC
 SG_ P2D_CMD2_Reserved2_13 : 20|3@1+ (1,0) [0|7] ""  DCDC
 SG_ P2D_CMD2_DCDCOutputCrrntSet_13 : 23|16@1+ (0.05,-2000) [-2000|1276.75] "A"  DCDC
 SG_ P2D_CMD2_DCDCOutputVltg_Set_13 : 39|12@1+ (0.1,-200) [-200|209.5] "V"  DCDC
 SG_ P2D_CMD2_Reserved3_13 : 51|4@1+ (1,0) [0|15] ""  DCDC
 SG_ P2D_CMD2_CommunicationState_13 : 55|2@1+ (1,0) [0|3] ""  DCDC
 SG_ P2D_CMD2_DCDC_Fault_Clear_13 : 57|1@1+ (1,0) [0|1] ""  DCDC
 SG_ P2D_CMD2_PCSOperationState_13 : 58|2@1+ (1,0) [0|3] ""  DCDC
 SG_ P2D_CMD2_DCDCLVoffControl_13 : 60|1@1+ (1,0) [0|1] ""  DCDC
 SG_ P2D_CMD2_Reserved4_13 : 61|3@1+ (1,0) [0|7] ""  DCDC

BO_ 2149416782 P2D_CMD2__14: 8 PC
 SG_ P2D_CMD2_CRC_14 : 0|8@1+ (1,0) [0|255] ""  DCDC
 SG_ P2D_CMD2_DCDCSerialNum_14 : 8|4@1+ (1,0) [0|15] ""  DCDC
 SG_ P2D_CMD2_DCDCEnable_14 : 12|1@1+ (1,0) [0|1] ""  DCDC
 SG_ P2D_CMD2_Reserved1_14 : 13|3@1+ (1,0) [0|7] ""  DCDC
 SG_ P2D_CMD2_DCDCWrkMdSwtch_14 : 16|2@1+ (1,0) [0|3] ""  DCDC
 SG_ P2D_CMD2_DCDCWrkMdSet_14 : 18|2@1+ (1,0) [0|3] ""  DCDC
 SG_ P2D_CMD2_Reserved2_14 : 20|3@1+ (1,0) [0|7] ""  DCDC
 SG_ P2D_CMD2_DCDCOutputCrrntSet_14 : 23|16@1+ (0.05,-2000) [-2000|1276.75] "A"  DCDC
 SG_ P2D_CMD2_DCDCOutputVltg_Set_14 : 39|12@1+ (0.1,-200) [-200|209.5] "V"  DCDC
 SG_ P2D_CMD2_Reserved3_14 : 51|4@1+ (1,0) [0|15] ""  DCDC
 SG_ P2D_CMD2_CommunicationState_14 : 55|2@1+ (1,0) [0|3] ""  DCDC
 SG_ P2D_CMD2_DCDC_Fault_Clear_14 : 57|1@1+ (1,0) [0|1] ""  DCDC
 SG_ P2D_CMD2_PCSOperationState_14 : 58|2@1+ (1,0) [0|3] ""  DCDC
 SG_ P2D_CMD2_DCDCLVoffControl_14 : 60|1@1+ (1,0) [0|1] ""  DCDC
 SG_ P2D_CMD2_Reserved4_14 : 61|3@1+ (1,0) [0|7] ""  DCDC

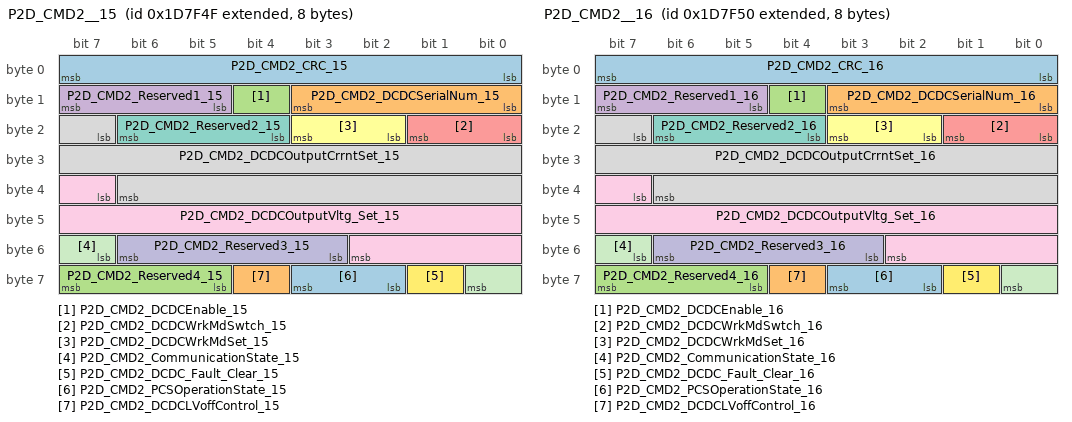
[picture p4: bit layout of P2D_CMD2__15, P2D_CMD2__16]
BO_ 2149416783 P2D_CMD2__15: 8 PC
 SG_ P2D_CMD2_CRC_15 : 0|8@1+ (1,0) [0|255] ""  DCDC
 SG_ P2D_CMD2_DCDCSerialNum_15 : 8|4@1+ (1,0) [0|15] ""  DCDC
 SG_ P2D_CMD2_DCDCEnable_15 : 12|1@1+ (1,0) [0|1] ""  DCDC
 SG_ P2D_CMD2_Reserved1_15 : 13|3@1+ (1,0) [0|7] ""  DCDC
 SG_ P2D_CMD2_DCDCWrkMdSwtch_15 : 16|2@1+ (1,0) [0|3] ""  DCDC
 SG_ P2D_CMD2_DCDCWrkMdSet_15 : 18|2@1+ (1,0) [0|3] ""  DCDC
 SG_ P2D_CMD2_Reserved2_15 : 20|3@1+ (1,0) [0|7] ""  DCDC
 SG_ P2D_CMD2_DCDCOutputCrrntSet_15 : 23|16@1+ (0.05,-2000) [-2000|1276.75] "A"  DCDC
 SG_ P2D_CMD2_DCDCOutputVltg_Set_15 : 39|12@1+ (0.1,-200) [-200|209.5] "V"  DCDC
 SG_ P2D_CMD2_Reserved3_15 : 51|4@1+ (1,0) [0|15] ""  DCDC
 SG_ P2D_CMD2_CommunicationState_15 : 55|2@1+ (1,0) [0|3] ""  DCDC
 SG_ P2D_CMD2_DCDC_Fault_Clear_15 : 57|1@1+ (1,0) [0|1] ""  DCDC
 SG_ P2D_CMD2_PCSOperationState_15 : 58|2@1+ (1,0) [0|3] ""  DCDC
 SG_ P2D_CMD2_DCDCLVoffControl_15 : 60|1@1+ (1,0) [0|1] ""  DCDC
 SG_ P2D_CMD2_Reserved4_15 : 61|3@1+ (1,0) [0|7] ""  DCDC

BO_ 2149416784 P2D_CMD2__16: 8 PC
 SG_ P2D_CMD2_CRC_16 : 0|8@1+ (1,0) [0|255] ""  DCDC
 SG_ P2D_CMD2_DCDCSerialNum_16 : 8|4@1+ (1,0) [0|15] ""  DCDC
 SG_ P2D_CMD2_DCDCEnable_16 : 12|1@1+ (1,0) [0|1] ""  DCDC
 SG_ P2D_CMD2_Reserved1_16 : 13|3@1+ (1,0) [0|7] ""  DCDC
 SG_ P2D_CMD2_DCDCWrkMdSwtch_16 : 16|2@1+ (1,0) [0|3] ""  DCDC
 SG_ P2D_CMD2_DCDCWrkMdSet_16 : 18|2@1+ (1,0) [0|3] ""  DCDC
 SG_ P2D_CMD2_Reserved2_16 : 20|3@1+ (1,0) [0|7] ""  DCDC
 SG_ P2D_CMD2_DCDCOutputCrrntSet_16 : 23|16@1+ (0.05,-2000) [-2000|1276.75] "A"  DCDC
 SG_ P2D_CMD2_DCDCOutputVltg_Set_16 : 39|12@1+ (0.1,-200) [-200|209.5] "V"  DCDC
 SG_ P2D_CMD2_Reserved3_16 : 51|4@1+ (1,0) [0|15] ""  DCDC
 SG_ P2D_CMD2_CommunicationState_16 : 55|2@1+ (1,0) [0|3] ""  DCDC
 SG_ P2D_CMD2_DCDC_Fault_Clear_16 : 57|1@1+ (1,0) [0|1] ""  DCDC
 SG_ P2D_CMD2_PCSOperationState_16 : 58|2@1+ (1,0) [0|3] ""  DCDC
 SG_ P2D_CMD2_DCDCLVoffControl_16 : 60|1@1+ (1,0) [0|1] ""  DCDC
 SG_ P2D_CMD2_Reserved4_16 : 61|3@1+ (1,0) [0|7] ""  DCDC

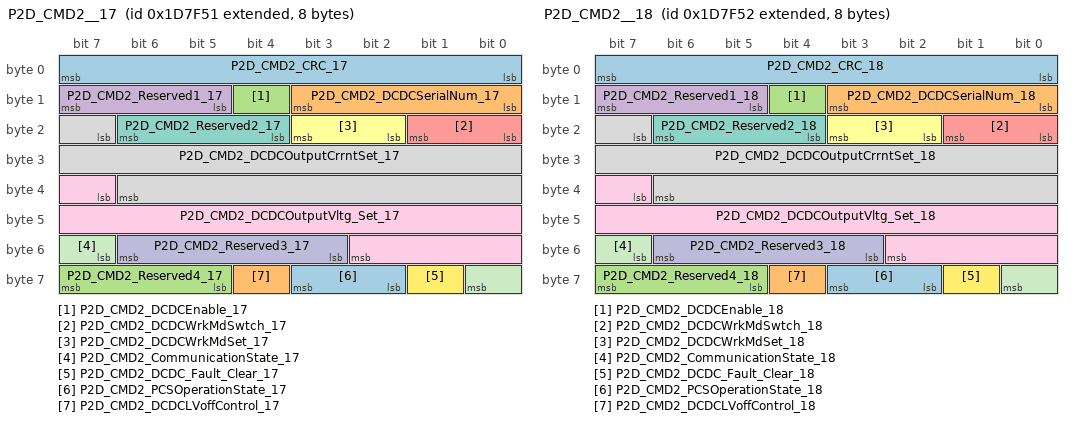
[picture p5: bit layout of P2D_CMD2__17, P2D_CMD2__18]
BO_ 2149416785 P2D_CMD2__17: 8 PC
 SG_ P2D_CMD2_CRC_17 : 0|8@1+ (1,0) [0|255] ""  DCDC
 SG_ P2D_CMD2_DCDCSerialNum_17 : 8|4@1+ (1,0) [0|15] ""  DCDC
 SG_ P2D_CMD2_DCDCEnable_17 : 12|1@1+ (1,0) [0|1] ""  DCDC
 SG_ P2D_CMD2_Reserved1_17 : 13|3@1+ (1,0) [0|7] ""  DCDC
 SG_ P2D_CMD2_DCDCWrkMdSwtch_17 : 16|2@1+ (1,0) [0|3] ""  DCDC
 SG_ P2D_CMD2_DCDCWrkMdSet_17 : 18|2@1+ (1,0) [0|3] ""  DCDC
 SG_ P2D_CMD2_Reserved2_17 : 20|3@1+ (1,0) [0|7] ""  DCDC
 SG_ P2D_CMD2_DCDCOutputCrrntSet_17 : 23|16@1+ (0.05,-2000) [-2000|1276.75] "A"  DCDC
 SG_ P2D_CMD2_DCDCOutputVltg_Set_17 : 39|12@1+ (0.1,-200) [-200|209.5] "V"  DCDC
 SG_ P2D_CMD2_Reserved3_17 : 51|4@1+ (1,0) [0|15] ""  DCDC
 SG_ P2D_CMD2_CommunicationState_17 : 55|2@1+ (1,0) [0|3] ""  DCDC
 SG_ P2D_CMD2_DCDC_Fault_Clear_17 : 57|1@1+ (1,0) [0|1] ""  DCDC
 SG_ P2D_CMD2_PCSOperationState_17 : 58|2@1+ (1,0) [0|3] ""  DCDC
 SG_ P2D_CMD2_DCDCLVoffControl_17 : 60|1@1+ (1,0) [0|1] ""  DCDC
 SG_ P2D_CMD2_Reserved4_17 : 61|3@1+ (1,0) [0|7] ""  DCDC

BO_ 2149416786 P2D_CMD2__18: 8 PC
 SG_ P2D_CMD2_CRC_18 : 0|8@1+ (1,0) [0|255] ""  DCDC
 SG_ P2D_CMD2_DCDCSerialNum_18 : 8|4@1+ (1,0) [0|15] ""  DCDC
 SG_ P2D_CMD2_DCDCEnable_18 : 12|1@1+ (1,0) [0|1] ""  DCDC
 SG_ P2D_CMD2_Reserved1_18 : 13|3@1+ (1,0) [0|7] ""  DCDC
 SG_ P2D_CMD2_DCDCWrkMdSwtch_18 : 16|2@1+ (1,0) [0|3] ""  DCDC
 SG_ P2D_CMD2_DCDCWrkMdSet_18 : 18|2@1+ (1,0) [0|3] ""  DCDC
 SG_ P2D_CMD2_Reserved2_18 : 20|3@1+ (1,0) [0|7] ""  DCDC
 SG_ P2D_CMD2_DCDCOutputCrrntSet_18 : 23|16@1+ (0.05,-2000) [-2000|1276.75] "A"  DCDC
 SG_ P2D_CMD2_DCDCOutputVltg_Set_18 : 39|12@1+ (0.1,-200) [-200|209.5] "V"  DCDC
 SG_ P2D_CMD2_Reserved3_18 : 51|4@1+ (1,0) [0|15] ""  DCDC
 SG_ P2D_CMD2_CommunicationState_18 : 55|2@1+ (1,0) [0|3] ""  DCDC
 SG_ P2D_CMD2_DCDC_Fault_Clear_18 : 57|1@1+ (1,0) [0|1] ""  DCDC
 SG_ P2D_CMD2_PCSOperationState_18 : 58|2@1+ (1,0) [0|3] ""  DCDC
 SG_ P2D_CMD2_DCDCLVoffControl_18 : 60|1@1+ (1,0) [0|1] ""  DCDC
 SG_ P2D_CMD2_Reserved4_18 : 61|3@1+ (1,0) [0|7] ""  DCDC

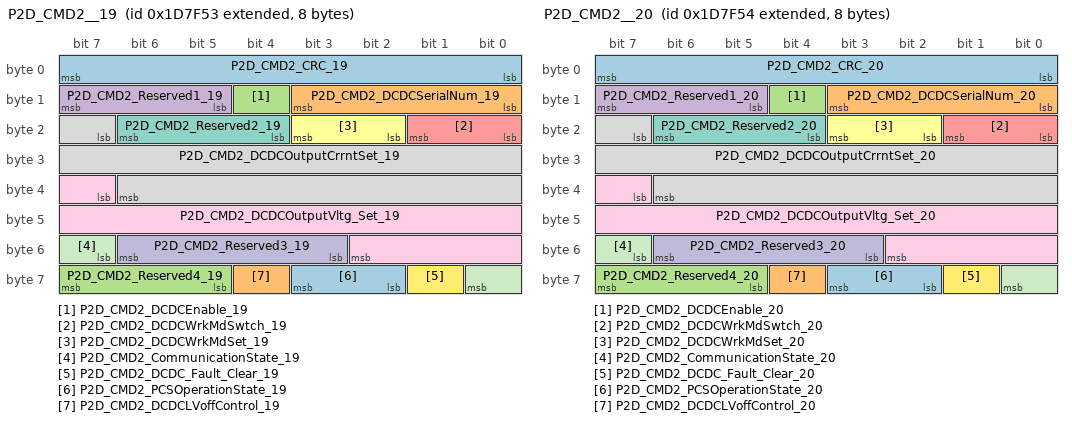
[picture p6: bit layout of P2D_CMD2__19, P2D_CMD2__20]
BO_ 2149416787 P2D_CMD2__19: 8 PC
 SG_ P2D_CMD2_CRC_19 : 0|8@1+ (1,0) [0|255] ""  DCDC
 SG_ P2D_CMD2_DCDCSerialNum_19 : 8|4@1+ (1,0) [0|15] ""  DCDC
 SG_ P2D_CMD2_DCDCEnable_19 : 12|1@1+ (1,0) [0|1] ""  DCDC
 SG_ P2D_CMD2_Reserved1_19 : 13|3@1+ (1,0) [0|7] ""  DCDC
 SG_ P2D_CMD2_DCDCWrkMdSwtch_19 : 16|2@1+ (1,0) [0|3] ""  DCDC
 SG_ P2D_CMD2_DCDCWrkMdSet_19 : 18|2@1+ (1,0) [0|3] ""  DCDC
 SG_ P2D_CMD2_Reserved2_19 : 20|3@1+ (1,0) [0|7] ""  DCDC
 SG_ P2D_CMD2_DCDCOutputCrrntSet_19 : 23|16@1+ (0.05,-2000) [-2000|1276.75] "A"  DCDC
 SG_ P2D_CMD2_DCDCOutputVltg_Set_19 : 39|12@1+ (0.1,-200) [-200|209.5] "V"  DCDC
 SG_ P2D_CMD2_Reserved3_19 : 51|4@1+ (1,0) [0|15] ""  DCDC
 SG_ P2D_CMD2_CommunicationState_19 : 55|2@1+ (1,0) [0|3] ""  DCDC
 SG_ P2D_CMD2_DCDC_Fault_Clear_19 : 57|1@1+ (1,0) [0|1] ""  DCDC
 SG_ P2D_CMD2_PCSOperationState_19 : 58|2@1+ (1,0) [0|3] ""  DCDC
 SG_ P2D_CMD2_DCDCLVoffControl_19 : 60|1@1+ (1,0) [0|1] ""  DCDC
 SG_ P2D_CMD2_Reserved4_19 : 61|3@1+ (1,0) [0|7] ""  DCDC

BO_ 2149416788 P2D_CMD2__20: 8 PC
 SG_ P2D_CMD2_CRC_20 : 0|8@1+ (1,0) [0|255] ""  DCDC
 SG_ P2D_CMD2_DCDCSerialNum_20 : 8|4@1+ (1,0) [0|15] ""  DCDC
 SG_ P2D_CMD2_DCDCEnable_20 : 12|1@1+ (1,0) [0|1] ""  DCDC
 SG_ P2D_CMD2_Reserved1_20 : 13|3@1+ (1,0) [0|7] ""  DCDC
 SG_ P2D_CMD2_DCDCWrkMdSwtch_20 : 16|2@1+ (1,0) [0|3] ""  DCDC
 SG_ P2D_CMD2_DCDCWrkMdSet_20 : 18|2@1+ (1,0) [0|3] ""  DCDC
 SG_ P2D_CMD2_Reserved2_20 : 20|3@1+ (1,0) [0|7] ""  DCDC
 SG_ P2D_CMD2_DCDCOutputCrrntSet_20 : 23|16@1+ (0.05,-2000) [-2000|1276.75] "A"  DCDC
 SG_ P2D_CMD2_DCDCOutputVltg_Set_20 : 39|12@1+ (0.1,-200) [-200|209.5] "V"  DCDC
 SG_ P2D_CMD2_Reserved3_20 : 51|4@1+ (1,0) [0|15] ""  DCDC
 SG_ P2D_CMD2_CommunicationState_20 : 55|2@1+ (1,0) [0|3] ""  DCDC
 SG_ P2D_CMD2_DCDC_Fault_Clear_20 : 57|1@1+ (1,0) [0|1] ""  DCDC
 SG_ P2D_CMD2_PCSOperationState_20 : 58|2@1+ (1,0) [0|3] ""  DCDC
 SG_ P2D_CMD2_DCDCLVoffControl_20 : 60|1@1+ (1,0) [0|1] ""  DCDC
 SG_ P2D_CMD2_Reserved4_20 : 61|3@1+ (1,0) [0|7] ""  DCDC

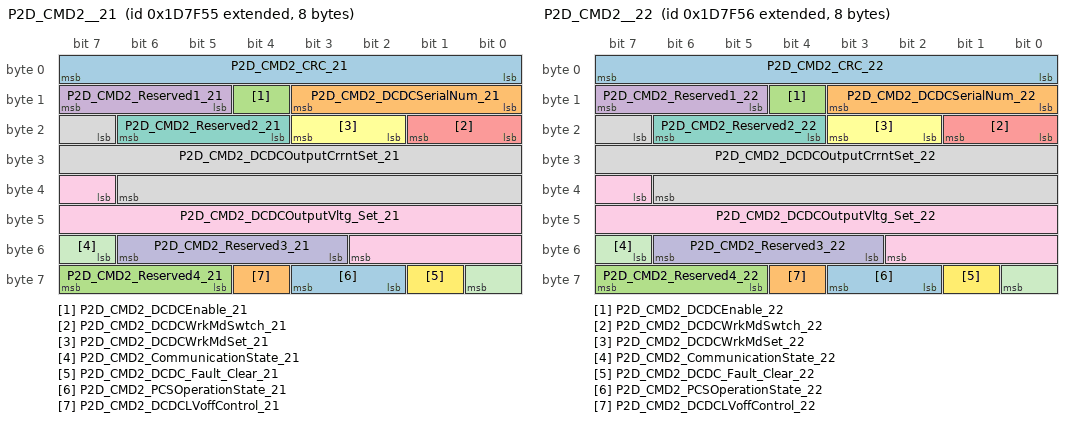
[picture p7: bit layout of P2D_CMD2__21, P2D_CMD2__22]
BO_ 2149416789 P2D_CMD2__21: 8 PC
 SG_ P2D_CMD2_CRC_21 : 0|8@1+ (1,0) [0|255] ""  DCDC
 SG_ P2D_CMD2_DCDCSerialNum_21 : 8|4@1+ (1,0) [0|15] ""  DCDC
 SG_ P2D_CMD2_DCDCEnable_21 : 12|1@1+ (1,0) [0|1] ""  DCDC
 SG_ P2D_CMD2_Reserved1_21 : 13|3@1+ (1,0) [0|7] ""  DCDC
 SG_ P2D_CMD2_DCDCWrkMdSwtch_21 : 16|2@1+ (1,0) [0|3] ""  DCDC
 SG_ P2D_CMD2_DCDCWrkMdSet_21 : 18|2@1+ (1,0) [0|3] ""  DCDC
 SG_ P2D_CMD2_Reserved2_21 : 20|3@1+ (1,0) [0|7] ""  DCDC
 SG_ P2D_CMD2_DCDCOutputCrrntSet_21 : 23|16@1+ (0.05,-2000) [-2000|1276.75] "A"  DCDC
 SG_ P2D_CMD2_DCDCOutputVltg_Set_21 : 39|12@1+ (0.1,-200) [-200|209.5] "V"  DCDC
 SG_ P2D_CMD2_Reserved3_21 : 51|4@1+ (1,0) [0|15] ""  DCDC
 SG_ P2D_CMD2_CommunicationState_21 : 55|2@1+ (1,0) [0|3] ""  DCDC
 SG_ P2D_CMD2_DCDC_Fault_Clear_21 : 57|1@1+ (1,0) [0|1] ""  DCDC
 SG_ P2D_CMD2_PCSOperationState_21 : 58|2@1+ (1,0) [0|3] ""  DCDC
 SG_ P2D_CMD2_DCDCLVoffControl_21 : 60|1@1+ (1,0) [0|1] ""  DCDC
 SG_ P2D_CMD2_Reserved4_21 : 61|3@1+ (1,0) [0|7] ""  DCDC

BO_ 2149416790 P2D_CMD2__22: 8 PC
 SG_ P2D_CMD2_CRC_22 : 0|8@1+ (1,0) [0|255] ""  DCDC
 SG_ P2D_CMD2_DCDCSerialNum_22 : 8|4@1+ (1,0) [0|15] ""  DCDC
 SG_ P2D_CMD2_DCDCEnable_22 : 12|1@1+ (1,0) [0|1] ""  DCDC
 SG_ P2D_CMD2_Reserved1_22 : 13|3@1+ (1,0) [0|7] ""  DCDC
 SG_ P2D_CMD2_DCDCWrkMdSwtch_22 : 16|2@1+ (1,0) [0|3] ""  DCDC
 SG_ P2D_CMD2_DCDCWrkMdSet_22 : 18|2@1+ (1,0) [0|3] ""  DCDC
 SG_ P2D_CMD2_Reserved2_22 : 20|3@1+ (1,0) [0|7] ""  DCDC
 SG_ P2D_CMD2_DCDCOutputCrrntSet_22 : 23|16@1+ (0.05,-2000) [-2000|1276.75] "A"  DCDC
 SG_ P2D_CMD2_DCDCOutputVltg_Set_22 : 39|12@1+ (0.1,-200) [-200|209.5] "V"  DCDC
 SG_ P2D_CMD2_Reserved3_22 : 51|4@1+ (1,0) [0|15] ""  DCDC
 SG_ P2D_CMD2_CommunicationState_22 : 55|2@1+ (1,0) [0|3] ""  DCDC
 SG_ P2D_CMD2_DCDC_Fault_Clear_22 : 57|1@1+ (1,0) [0|1] ""  DCDC
 SG_ P2D_CMD2_PCSOperationState_22 : 58|2@1+ (1,0) [0|3] ""  DCDC
 SG_ P2D_CMD2_DCDCLVoffControl_22 : 60|1@1+ (1,0) [0|1] ""  DCDC
 SG_ P2D_CMD2_Reserved4_22 : 61|3@1+ (1,0) [0|7] ""  DCDC

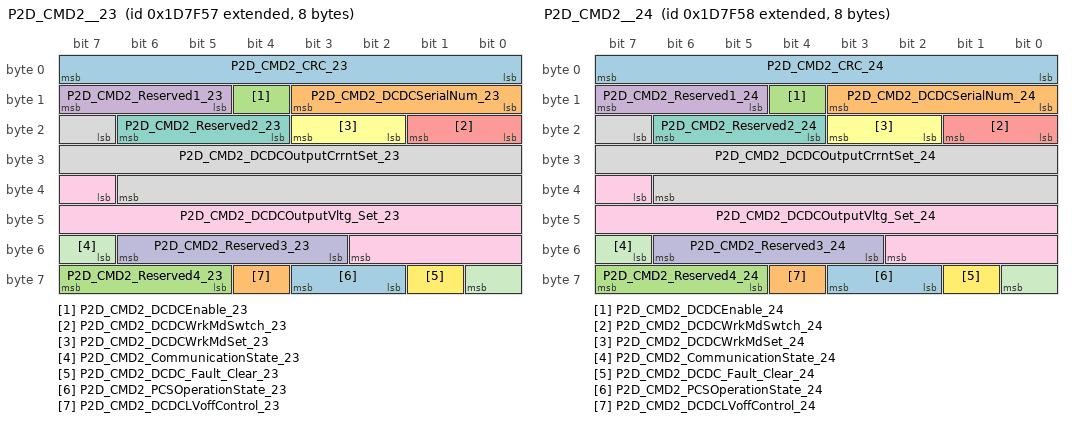
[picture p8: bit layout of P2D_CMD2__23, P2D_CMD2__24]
BO_ 2149416791 P2D_CMD2__23: 8 PC
 SG_ P2D_CMD2_CRC_23 : 0|8@1+ (1,0) [0|255] ""  DCDC
 SG_ P2D_CMD2_DCDCSerialNum_23 : 8|4@1+ (1,0) [0|15] ""  DCDC
 SG_ P2D_CMD2_DCDCEnable_23 : 12|1@1+ (1,0) [0|1] ""  DCDC
 SG_ P2D_CMD2_Reserved1_23 : 13|3@1+ (1,0) [0|7] ""  DCDC
 SG_ P2D_CMD2_DCDCWrkMdSwtch_23 : 16|2@1+ (1,0) [0|3] ""  DCDC
 SG_ P2D_CMD2_DCDCWrkMdSet_23 : 18|2@1+ (1,0) [0|3] ""  DCDC
 SG_ P2D_CMD2_Reserved2_23 : 20|3@1+ (1,0) [0|7] ""  DCDC
 SG_ P2D_CMD2_DCDCOutputCrrntSet_23 : 23|16@1+ (0.05,-2000) [-2000|1276.75] "A"  DCDC
 SG_ P2D_CMD2_DCDCOutputVltg_Set_23 : 39|12@1+ (0.1,-200) [-200|209.5] "V"  DCDC
 SG_ P2D_CMD2_Reserved3_23 : 51|4@1+ (1,0) [0|15] ""  DCDC
 SG_ P2D_CMD2_CommunicationState_23 : 55|2@1+ (1,0) [0|3] ""  DCDC
 SG_ P2D_CMD2_DCDC_Fault_Clear_23 : 57|1@1+ (1,0) [0|1] ""  DCDC
 SG_ P2D_CMD2_PCSOperationState_23 : 58|2@1+ (1,0) [0|3] ""  DCDC
 SG_ P2D_CMD2_DCDCLVoffControl_23 : 60|1@1+ (1,0) [0|1] ""  DCDC
 SG_ P2D_CMD2_Reserved4_23 : 61|3@1+ (1,0) [0|7] ""  DCDC

BO_ 2149416792 P2D_CMD2__24: 8 PC
 SG_ P2D_CMD2_CRC_24 : 0|8@1+ (1,0) [0|255] ""  DCDC
 SG_ P2D_CMD2_DCDCSerialNum_24 : 8|4@1+ (1,0) [0|15] ""  DCDC
 SG_ P2D_CMD2_DCDCEnable_24 : 12|1@1+ (1,0) [0|1] ""  DCDC
 SG_ P2D_CMD2_Reserved1_24 : 13|3@1+ (1,0) [0|7] ""  DCDC
 SG_ P2D_CMD2_DCDCWrkMdSwtch_24 : 16|2@1+ (1,0) [0|3] ""  DCDC
 SG_ P2D_CMD2_DCDCWrkMdSet_24 : 18|2@1+ (1,0) [0|3] ""  DCDC
 SG_ P2D_CMD2_Reserved2_24 : 20|3@1+ (1,0) [0|7] ""  DCDC
 SG_ P2D_CMD2_DCDCOutputCrrntSet_24 : 23|16@1+ (0.05,-2000) [-2000|1276.75] "A"  DCDC
 SG_ P2D_CMD2_DCDCOutputVltg_Set_24 : 39|12@1+ (0.1,-200) [-200|209.5] "V"  DCDC
 SG_ P2D_CMD2_Reserved3_24 : 51|4@1+ (1,0) [0|15] ""  DCDC
 SG_ P2D_CMD2_CommunicationState_24 : 55|2@1+ (1,0) [0|3] ""  DCDC
 SG_ P2D_CMD2_DCDC_Fault_Clear_24 : 57|1@1+ (1,0) [0|1] ""  DCDC
 SG_ P2D_CMD2_PCSOperationState_24 : 58|2@1+ (1,0) [0|3] ""  DCDC
 SG_ P2D_CMD2_DCDCLVoffControl_24 : 60|1@1+ (1,0) [0|1] ""  DCDC
 SG_ P2D_CMD2_Reserved4_24 : 61|3@1+ (1,0) [0|7] ""  DCDC

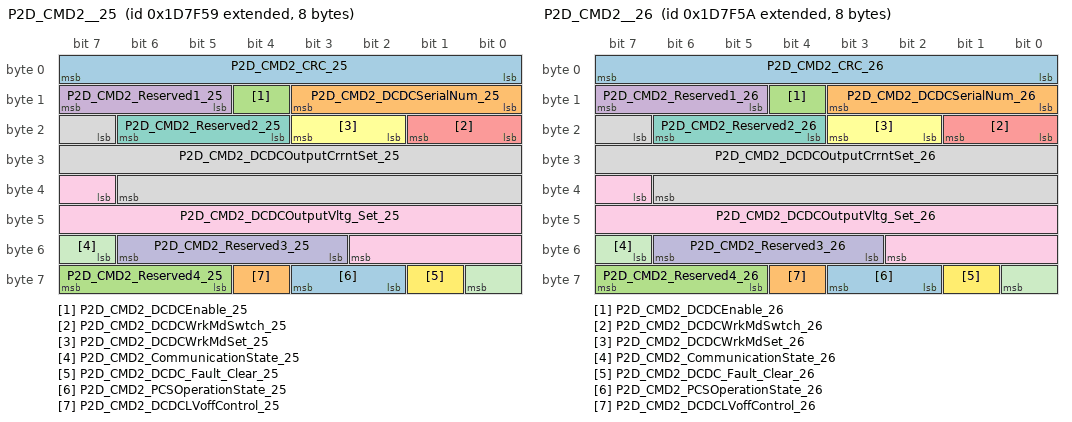
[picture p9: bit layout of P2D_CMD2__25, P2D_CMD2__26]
BO_ 2149416793 P2D_CMD2__25: 8 PC
 SG_ P2D_CMD2_CRC_25 : 0|8@1+ (1,0) [0|255] ""  DCDC
 SG_ P2D_CMD2_DCDCSerialNum_25 : 8|4@1+ (1,0) [0|15] ""  DCDC
 SG_ P2D_CMD2_DCDCEnable_25 : 12|1@1+ (1,0) [0|1] ""  DCDC
 SG_ P2D_CMD2_Reserved1_25 : 13|3@1+ (1,0) [0|7] ""  DCDC
 SG_ P2D_CMD2_DCDCWrkMdSwtch_25 : 16|2@1+ (1,0) [0|3] ""  DCDC
 SG_ P2D_CMD2_DCDCWrkMdSet_25 : 18|2@1+ (1,0) [0|3] ""  DCDC
 SG_ P2D_CMD2_Reserved2_25 : 20|3@1+ (1,0) [0|7] ""  DCDC
 SG_ P2D_CMD2_DCDCOutputCrrntSet_25 : 23|16@1+ (0.05,-2000) [-2000|1276.75] "A"  DCDC
 SG_ P2D_CMD2_DCDCOutputVltg_Set_25 : 39|12@1+ (0.1,-200) [-200|209.5] "V"  DCDC
 SG_ P2D_CMD2_Reserved3_25 : 51|4@1+ (1,0) [0|15] ""  DCDC
 SG_ P2D_CMD2_CommunicationState_25 : 55|2@1+ (1,0) [0|3] ""  DCDC
 SG_ P2D_CMD2_DCDC_Fault_Clear_25 : 57|1@1+ (1,0) [0|1] ""  DCDC
 SG_ P2D_CMD2_PCSOperationState_25 : 58|2@1+ (1,0) [0|3] ""  DCDC
 SG_ P2D_CMD2_DCDCLVoffControl_25 : 60|1@1+ (1,0) [0|1] ""  DCDC
 SG_ P2D_CMD2_Reserved4_25 : 61|3@1+ (1,0) [0|7] ""  DCDC

BO_ 2149416794 P2D_CMD2__26: 8 PC
 SG_ P2D_CMD2_CRC_26 : 0|8@1+ (1,0) [0|255] ""  DCDC
 SG_ P2D_CMD2_DCDCSerialNum_26 : 8|4@1+ (1,0) [0|15] ""  DCDC
 SG_ P2D_CMD2_DCDCEnable_26 : 12|1@1+ (1,0) [0|1] ""  DCDC
 SG_ P2D_CMD2_Reserved1_26 : 13|3@1+ (1,0) [0|7] ""  DCDC
 SG_ P2D_CMD2_DCDCWrkMdSwtch_26 : 16|2@1+ (1,0) [0|3] ""  DCDC
 SG_ P2D_CMD2_DCDCWrkMdSet_26 : 18|2@1+ (1,0) [0|3] ""  DCDC
 SG_ P2D_CMD2_Reserved2_26 : 20|3@1+ (1,0) [0|7] ""  DCDC
 SG_ P2D_CMD2_DCDCOutputCrrntSet_26 : 23|16@1+ (0.05,-2000) [-2000|1276.75] "A"  DCDC
 SG_ P2D_CMD2_DCDCOutputVltg_Set_26 : 39|12@1+ (0.1,-200) [-200|209.5] "V"  DCDC
 SG_ P2D_CMD2_Reserved3_26 : 51|4@1+ (1,0) [0|15] ""  DCDC
 SG_ P2D_CMD2_CommunicationState_26 : 55|2@1+ (1,0) [0|3] ""  DCDC
 SG_ P2D_CMD2_DCDC_Fault_Clear_26 : 57|1@1+ (1,0) [0|1] ""  DCDC
 SG_ P2D_CMD2_PCSOperationState_26 : 58|2@1+ (1,0) [0|3] ""  DCDC
 SG_ P2D_CMD2_DCDCLVoffControl_26 : 60|1@1+ (1,0) [0|1] ""  DCDC
 SG_ P2D_CMD2_Reserved4_26 : 61|3@1+ (1,0) [0|7] ""  DCDC

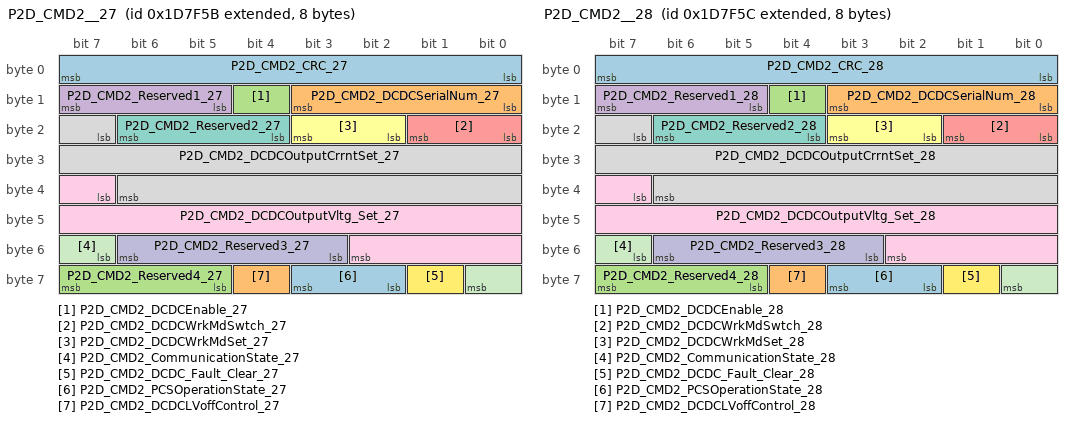
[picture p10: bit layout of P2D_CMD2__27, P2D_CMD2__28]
BO_ 2149416795 P2D_CMD2__27: 8 PC
 SG_ P2D_CMD2_CRC_27 : 0|8@1+ (1,0) [0|255] ""  DCDC
 SG_ P2D_CMD2_DCDCSerialNum_27 : 8|4@1+ (1,0) [0|15] ""  DCDC
 SG_ P2D_CMD2_DCDCEnable_27 : 12|1@1+ (1,0) [0|1] ""  DCDC
 SG_ P2D_CMD2_Reserved1_27 : 13|3@1+ (1,0) [0|7] ""  DCDC
 SG_ P2D_CMD2_DCDCWrkMdSwtch_27 : 16|2@1+ (1,0) [0|3] ""  DCDC
 SG_ P2D_CMD2_DCDCWrkMdSet_27 : 18|2@1+ (1,0) [0|3] ""  DCDC
 SG_ P2D_CMD2_Reserved2_27 : 20|3@1+ (1,0) [0|7] ""  DCDC
 SG_ P2D_CMD2_DCDCOutputCrrntSet_27 : 23|16@1+ (0.05,-2000) [-2000|1276.75] "A"  DCDC
 SG_ P2D_CMD2_DCDCOutputVltg_Set_27 : 39|12@1+ (0.1,-200) [-200|209.5] "V"  DCDC
 SG_ P2D_CMD2_Reserved3_27 : 51|4@1+ (1,0) [0|15] ""  DCDC
 SG_ P2D_CMD2_CommunicationState_27 : 55|2@1+ (1,0) [0|3] ""  DCDC
 SG_ P2D_CMD2_DCDC_Fault_Clear_27 : 57|1@1+ (1,0) [0|1] ""  DCDC
 SG_ P2D_CMD2_PCSOperationState_27 : 58|2@1+ (1,0) [0|3] ""  DCDC
 SG_ P2D_CMD2_DCDCLVoffControl_27 : 60|1@1+ (1,0) [0|1] ""  DCDC
 SG_ P2D_CMD2_Reserved4_27 : 61|3@1+ (1,0) [0|7] ""  DCDC

BO_ 2149416796 P2D_CMD2__28: 8 PC
 SG_ P2D_CMD2_CRC_28 : 0|8@1+ (1,0) [0|255] ""  DCDC
 SG_ P2D_CMD2_DCDCSerialNum_28 : 8|4@1+ (1,0) [0|15] ""  DCDC
 SG_ P2D_CMD2_DCDCEnable_28 : 12|1@1+ (1,0) [0|1] ""  DCDC
 SG_ P2D_CMD2_Reserved1_28 : 13|3@1+ (1,0) [0|7] ""  DCDC
 SG_ P2D_CMD2_DCDCWrkMdSwtch_28 : 16|2@1+ (1,0) [0|3] ""  DCDC
 SG_ P2D_CMD2_DCDCWrkMdSet_28 : 18|2@1+ (1,0) [0|3] ""  DCDC
 SG_ P2D_CMD2_Reserved2_28 : 20|3@1+ (1,0) [0|7] ""  DCDC
 SG_ P2D_CMD2_DCDCOutputCrrntSet_28 : 23|16@1+ (0.05,-2000) [-2000|1276.75] "A"  DCDC
 SG_ P2D_CMD2_DCDCOutputVltg_Set_28 : 39|12@1+ (0.1,-200) [-200|209.5] "V"  DCDC
 SG_ P2D_CMD2_Reserved3_28 : 51|4@1+ (1,0) [0|15] ""  DCDC
 SG_ P2D_CMD2_CommunicationState_28 : 55|2@1+ (1,0) [0|3] ""  DCDC
 SG_ P2D_CMD2_DCDC_Fault_Clear_28 : 57|1@1+ (1,0) [0|1] ""  DCDC
 SG_ P2D_CMD2_PCSOperationState_28 : 58|2@1+ (1,0) [0|3] ""  DCDC
 SG_ P2D_CMD2_DCDCLVoffControl_28 : 60|1@1+ (1,0) [0|1] ""  DCDC
 SG_ P2D_CMD2_Reserved4_28 : 61|3@1+ (1,0) [0|7] ""  DCDC

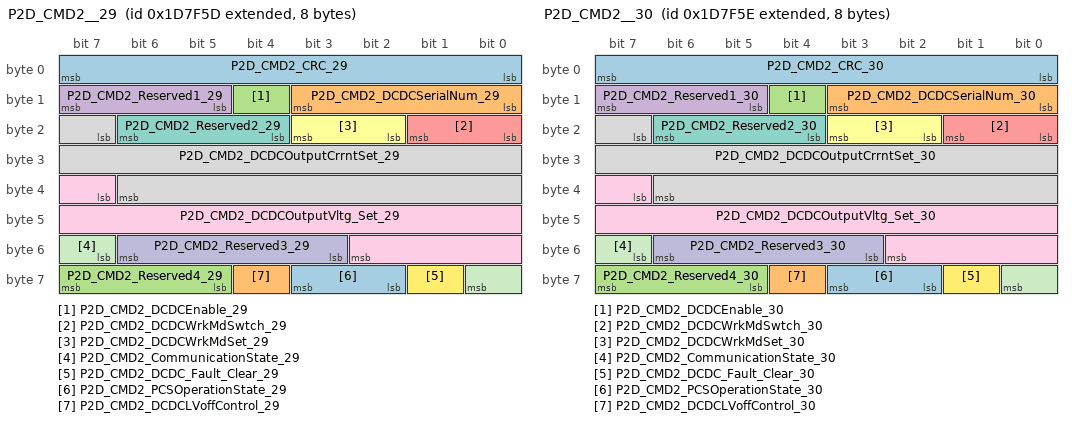
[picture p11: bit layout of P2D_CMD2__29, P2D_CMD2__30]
BO_ 2149416797 P2D_CMD2__29: 8 PC
 SG_ P2D_CMD2_CRC_29 : 0|8@1+ (1,0) [0|255] ""  DCDC
 SG_ P2D_CMD2_DCDCSerialNum_29 : 8|4@1+ (1,0) [0|15] ""  DCDC
 SG_ P2D_CMD2_DCDCEnable_29 : 12|1@1+ (1,0) [0|1] ""  DCDC
 SG_ P2D_CMD2_Reserved1_29 : 13|3@1+ (1,0) [0|7] ""  DCDC
 SG_ P2D_CMD2_DCDCWrkMdSwtch_29 : 16|2@1+ (1,0) [0|3] ""  DCDC
 SG_ P2D_CMD2_DCDCWrkMdSet_29 : 18|2@1+ (1,0) [0|3] ""  DCDC
 SG_ P2D_CMD2_Reserved2_29 : 20|3@1+ (1,0) [0|7] ""  DCDC
 SG_ P2D_CMD2_DCDCOutputCrrntSet_29 : 23|16@1+ (0.05,-2000) [-2000|1276.75] "A"  DCDC
 SG_ P2D_CMD2_DCDCOutputVltg_Set_29 : 39|12@1+ (0.1,-200) [-200|209.5] "V"  DCDC
 SG_ P2D_CMD2_Reserved3_29 : 51|4@1+ (1,0) [0|15] ""  DCDC
 SG_ P2D_CMD2_CommunicationState_29 : 55|2@1+ (1,0) [0|3] ""  DCDC
 SG_ P2D_CMD2_DCDC_Fault_Clear_29 : 57|1@1+ (1,0) [0|1] ""  DCDC
 SG_ P2D_CMD2_PCSOperationState_29 : 58|2@1+ (1,0) [0|3] ""  DCDC
 SG_ P2D_CMD2_DCDCLVoffControl_29 : 60|1@1+ (1,0) [0|1] ""  DCDC
 SG_ P2D_CMD2_Reserved4_29 : 61|3@1+ (1,0) [0|7] ""  DCDC

BO_ 2149416798 P2D_CMD2__30: 8 PC
 SG_ P2D_CMD2_CRC_30 : 0|8@1+ (1,0) [0|255] ""  DCDC
 SG_ P2D_CMD2_DCDCSerialNum_30 : 8|4@1+ (1,0) [0|15] ""  DCDC
 SG_ P2D_CMD2_DCDCEnable_30 : 12|1@1+ (1,0) [0|1] ""  DCDC
 SG_ P2D_CMD2_Reserved1_30 : 13|3@1+ (1,0) [0|7] ""  DCDC
 SG_ P2D_CMD2_DCDCWrkMdSwtch_30 : 16|2@1+ (1,0) [0|3] ""  DCDC
 SG_ P2D_CMD2_DCDCWrkMdSet_30 : 18|2@1+ (1,0) [0|3] ""  DCDC
 SG_ P2D_CMD2_Reserved2_30 : 20|3@1+ (1,0) [0|7] ""  DCDC
 SG_ P2D_CMD2_DCDCOutputCrrntSet_30 : 23|16@1+ (0.05,-2000) [-2000|1276.75] "A"  DCDC
 SG_ P2D_CMD2_DCDCOutputVltg_Set_30 : 39|12@1+ (0.1,-200) [-200|209.5] "V"  DCDC
 SG_ P2D_CMD2_Reserved3_30 : 51|4@1+ (1,0) [0|15] ""  DCDC
 SG_ P2D_CMD2_CommunicationState_30 : 55|2@1+ (1,0) [0|3] ""  DCDC
 SG_ P2D_CMD2_DCDC_Fault_Clear_30 : 57|1@1+ (1,0) [0|1] ""  DCDC
 SG_ P2D_CMD2_PCSOperationState_30 : 58|2@1+ (1,0) [0|3] ""  DCDC
 SG_ P2D_CMD2_DCDCLVoffControl_30 : 60|1@1+ (1,0) [0|1] ""  DCDC
 SG_ P2D_CMD2_Reserved4_30 : 61|3@1+ (1,0) [0|7] ""  DCDC

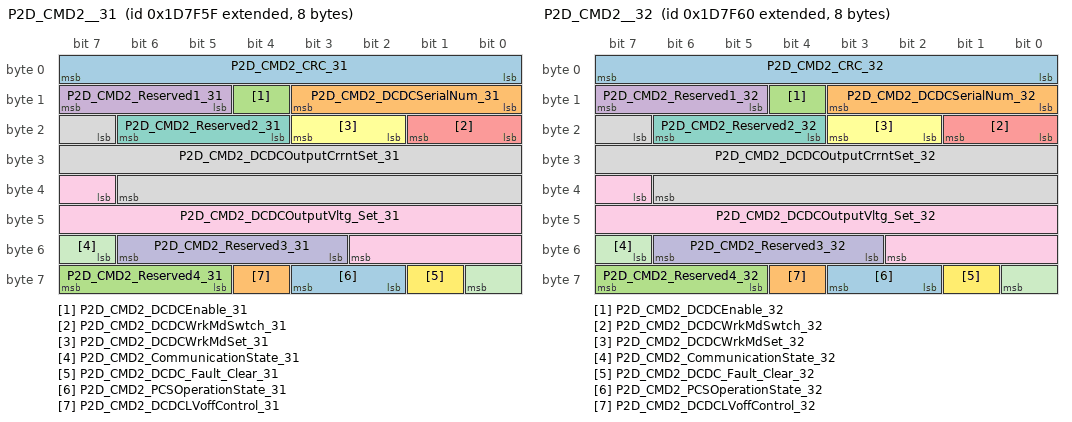
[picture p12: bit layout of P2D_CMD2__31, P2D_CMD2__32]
BO_ 2149416799 P2D_CMD2__31: 8 PC
 SG_ P2D_CMD2_CRC_31 : 0|8@1+ (1,0) [0|255] ""  DCDC
 SG_ P2D_CMD2_DCDCSerialNum_31 : 8|4@1+ (1,0) [0|15] ""  DCDC
 SG_ P2D_CMD2_DCDCEnable_31 : 12|1@1+ (1,0) [0|1] ""  DCDC
 SG_ P2D_CMD2_Reserved1_31 : 13|3@1+ (1,0) [0|7] ""  DCDC
 SG_ P2D_CMD2_DCDCWrkMdSwtch_31 : 16|2@1+ (1,0) [0|3] ""  DCDC
 SG_ P2D_CMD2_DCDCWrkMdSet_31 : 18|2@1+ (1,0) [0|3] ""  DCDC
 SG_ P2D_CMD2_Reserved2_31 : 20|3@1+ (1,0) [0|7] ""  DCDC
 SG_ P2D_CMD2_DCDCOutputCrrntSet_31 : 23|16@1+ (0.05,-2000) [-2000|1276.75] "A"  DCDC
 SG_ P2D_CMD2_DCDCOutputVltg_Set_31 : 39|12@1+ (0.1,-200) [-200|209.5] "V"  DCDC
 SG_ P2D_CMD2_Reserved3_31 : 51|4@1+ (1,0) [0|15] ""  DCDC
 SG_ P2D_CMD2_CommunicationState_31 : 55|2@1+ (1,0) [0|3] ""  DCDC
 SG_ P2D_CMD2_DCDC_Fault_Clear_31 : 57|1@1+ (1,0) [0|1] ""  DCDC
 SG_ P2D_CMD2_PCSOperationState_31 : 58|2@1+ (1,0) [0|3] ""  DCDC
 SG_ P2D_CMD2_DCDCLVoffControl_31 : 60|1@1+ (1,0) [0|1] ""  DCDC
 SG_ P2D_CMD2_Reserved4_31 : 61|3@1+ (1,0) [0|7] ""  DCDC

BO_ 2149416800 P2D_CMD2__32: 8 PC
 SG_ P2D_CMD2_CRC_32 : 0|8@1+ (1,0) [0|255] ""  DCDC
 SG_ P2D_CMD2_DCDCSerialNum_32 : 8|4@1+ (1,0) [0|15] ""  DCDC
 SG_ P2D_CMD2_DCDCEnable_32 : 12|1@1+ (1,0) [0|1] ""  DCDC
 SG_ P2D_CMD2_Reserved1_32 : 13|3@1+ (1,0) [0|7] ""  DCDC
 SG_ P2D_CMD2_DCDCWrkMdSwtch_32 : 16|2@1+ (1,0) [0|3] ""  DCDC
 SG_ P2D_CMD2_DCDCWrkMdSet_32 : 18|2@1+ (1,0) [0|3] ""  DCDC
 SG_ P2D_CMD2_Reserved2_32 : 20|3@1+ (1,0) [0|7] ""  DCDC
 SG_ P2D_CMD2_DCDCOutputCrrntSet_32 : 23|16@1+ (0.05,-2000) [-2000|1276.75] "A"  DCDC
 SG_ P2D_CMD2_DCDCOutputVltg_Set_32 : 39|12@1+ (0.1,-200) [-200|209.5] "V"  DCDC
 SG_ P2D_CMD2_Reserved3_32 : 51|4@1+ (1,0) [0|15] ""  DCDC
 SG_ P2D_CMD2_CommunicationState_32 : 55|2@1+ (1,0) [0|3] ""  DCDC
 SG_ P2D_CMD2_DCDC_Fault_Clear_32 : 57|1@1+ (1,0) [0|1] ""  DCDC
 SG_ P2D_CMD2_PCSOperationState_32 : 58|2@1+ (1,0) [0|3] ""  DCDC
 SG_ P2D_CMD2_DCDCLVoffControl_32 : 60|1@1+ (1,0) [0|1] ""  DCDC
 SG_ P2D_CMD2_Reserved4_32 : 61|3@1+ (1,0) [0|7] ""  DCDC

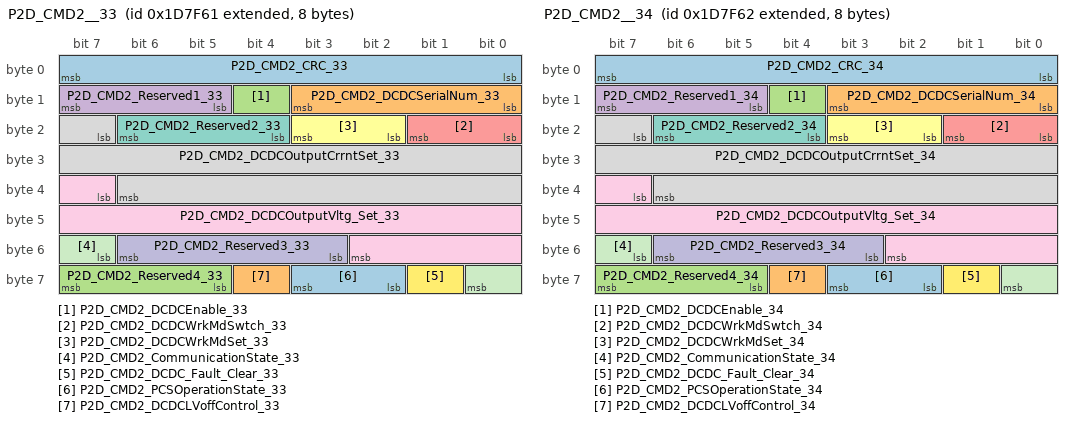
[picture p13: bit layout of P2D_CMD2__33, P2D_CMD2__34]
BO_ 2149416801 P2D_CMD2__33: 8 PC
 SG_ P2D_CMD2_CRC_33 : 0|8@1+ (1,0) [0|255] ""  DCDC
 SG_ P2D_CMD2_DCDCSerialNum_33 : 8|4@1+ (1,0) [0|15] ""  DCDC
 SG_ P2D_CMD2_DCDCEnable_33 : 12|1@1+ (1,0) [0|1] ""  DCDC
 SG_ P2D_CMD2_Reserved1_33 : 13|3@1+ (1,0) [0|7] ""  DCDC
 SG_ P2D_CMD2_DCDCWrkMdSwtch_33 : 16|2@1+ (1,0) [0|3] ""  DCDC
 SG_ P2D_CMD2_DCDCWrkMdSet_33 : 18|2@1+ (1,0) [0|3] ""  DCDC
 SG_ P2D_CMD2_Reserved2_33 : 20|3@1+ (1,0) [0|7] ""  DCDC
 SG_ P2D_CMD2_DCDCOutputCrrntSet_33 : 23|16@1+ (0.05,-2000) [-2000|1276.75] "A"  DCDC
 SG_ P2D_CMD2_DCDCOutputVltg_Set_33 : 39|12@1+ (0.1,-200) [-200|209.5] "V"  DCDC
 SG_ P2D_CMD2_Reserved3_33 : 51|4@1+ (1,0) [0|15] ""  DCDC
 SG_ P2D_CMD2_CommunicationState_33 : 55|2@1+ (1,0) [0|3] ""  DCDC
 SG_ P2D_CMD2_DCDC_Fault_Clear_33 : 57|1@1+ (1,0) [0|1] ""  DCDC
 SG_ P2D_CMD2_PCSOperationState_33 : 58|2@1+ (1,0) [0|3] ""  DCDC
 SG_ P2D_CMD2_DCDCLVoffControl_33 : 60|1@1+ (1,0) [0|1] ""  DCDC
 SG_ P2D_CMD2_Reserved4_33 : 61|3@1+ (1,0) [0|7] ""  DCDC

BO_ 2149416802 P2D_CMD2__34: 8 PC
 SG_ P2D_CMD2_CRC_34 : 0|8@1+ (1,0) [0|255] ""  DCDC
 SG_ P2D_CMD2_DCDCSerialNum_34 : 8|4@1+ (1,0) [0|15] ""  DCDC
 SG_ P2D_CMD2_DCDCEnable_34 : 12|1@1+ (1,0) [0|1] ""  DCDC
 SG_ P2D_CMD2_Reserved1_34 : 13|3@1+ (1,0) [0|7] ""  DCDC
 SG_ P2D_CMD2_DCDCWrkMdSwtch_34 : 16|2@1+ (1,0) [0|3] ""  DCDC
 SG_ P2D_CMD2_DCDCWrkMdSet_34 : 18|2@1+ (1,0) [0|3] ""  DCDC
 SG_ P2D_CMD2_Reserved2_34 : 20|3@1+ (1,0) [0|7] ""  DCDC
 SG_ P2D_CMD2_DCDCOutputCrrntSet_34 : 23|16@1+ (0.05,-2000) [-2000|1276.75] "A"  DCDC
 SG_ P2D_CMD2_DCDCOutputVltg_Set_34 : 39|12@1+ (0.1,-200) [-200|209.5] "V"  DCDC
 SG_ P2D_CMD2_Reserved3_34 : 51|4@1+ (1,0) [0|15] ""  DCDC
 SG_ P2D_CMD2_CommunicationState_34 : 55|2@1+ (1,0) [0|3] ""  DCDC
 SG_ P2D_CMD2_DCDC_Fault_Clear_34 : 57|1@1+ (1,0) [0|1] ""  DCDC
 SG_ P2D_CMD2_PCSOperationState_34 : 58|2@1+ (1,0) [0|3] ""  DCDC
 SG_ P2D_CMD2_DCDCLVoffControl_34 : 60|1@1+ (1,0) [0|1] ""  DCDC
 SG_ P2D_CMD2_Reserved4_34 : 61|3@1+ (1,0) [0|7] ""  DCDC

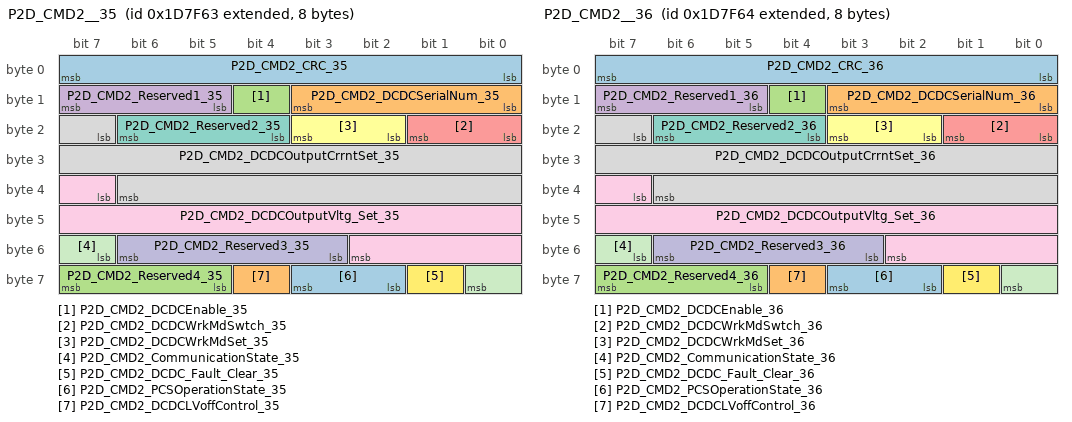
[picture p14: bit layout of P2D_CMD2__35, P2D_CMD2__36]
BO_ 2149416803 P2D_CMD2__35: 8 PC
 SG_ P2D_CMD2_CRC_35 : 0|8@1+ (1,0) [0|255] ""  DCDC
 SG_ P2D_CMD2_DCDCSerialNum_35 : 8|4@1+ (1,0) [0|15] ""  DCDC
 SG_ P2D_CMD2_DCDCEnable_35 : 12|1@1+ (1,0) [0|1] ""  DCDC
 SG_ P2D_CMD2_Reserved1_35 : 13|3@1+ (1,0) [0|7] ""  DCDC
 SG_ P2D_CMD2_DCDCWrkMdSwtch_35 : 16|2@1+ (1,0) [0|3] ""  DCDC
 SG_ P2D_CMD2_DCDCWrkMdSet_35 : 18|2@1+ (1,0) [0|3] ""  DCDC
 SG_ P2D_CMD2_Reserved2_35 : 20|3@1+ (1,0) [0|7] ""  DCDC
 SG_ P2D_CMD2_DCDCOutputCrrntSet_35 : 23|16@1+ (0.05,-2000) [-2000|1276.75] "A"  DCDC
 SG_ P2D_CMD2_DCDCOutputVltg_Set_35 : 39|12@1+ (0.1,-200) [-200|209.5] "V"  DCDC
 SG_ P2D_CMD2_Reserved3_35 : 51|4@1+ (1,0) [0|15] ""  DCDC
 SG_ P2D_CMD2_CommunicationState_35 : 55|2@1+ (1,0) [0|3] ""  DCDC
 SG_ P2D_CMD2_DCDC_Fault_Clear_35 : 57|1@1+ (1,0) [0|1] ""  DCDC
 SG_ P2D_CMD2_PCSOperationState_35 : 58|2@1+ (1,0) [0|3] ""  DCDC
 SG_ P2D_CMD2_DCDCLVoffControl_35 : 60|1@1+ (1,0) [0|1] ""  DCDC
 SG_ P2D_CMD2_Reserved4_35 : 61|3@1+ (1,0) [0|7] ""  DCDC

BO_ 2149416804 P2D_CMD2__36: 8 PC
 SG_ P2D_CMD2_CRC_36 : 0|8@1+ (1,0) [0|255] ""  DCDC
 SG_ P2D_CMD2_DCDCSerialNum_36 : 8|4@1+ (1,0) [0|15] ""  DCDC
 SG_ P2D_CMD2_DCDCEnable_36 : 12|1@1+ (1,0) [0|1] ""  DCDC
 SG_ P2D_CMD2_Reserved1_36 : 13|3@1+ (1,0) [0|7] ""  DCDC
 SG_ P2D_CMD2_DCDCWrkMdSwtch_36 : 16|2@1+ (1,0) [0|3] ""  DCDC
 SG_ P2D_CMD2_DCDCWrkMdSet_36 : 18|2@1+ (1,0) [0|3] ""  DCDC
 SG_ P2D_CMD2_Reserved2_36 : 20|3@1+ (1,0) [0|7] ""  DCDC
 SG_ P2D_CMD2_DCDCOutputCrrntSet_36 : 23|16@1+ (0.05,-2000) [-2000|1276.75] "A"  DCDC
 SG_ P2D_CMD2_DCDCOutputVltg_Set_36 : 39|12@1+ (0.1,-200) [-200|209.5] "V"  DCDC
 SG_ P2D_CMD2_Reserved3_36 : 51|4@1+ (1,0) [0|15] ""  DCDC
 SG_ P2D_CMD2_CommunicationState_36 : 55|2@1+ (1,0) [0|3] ""  DCDC
 SG_ P2D_CMD2_DCDC_Fault_Clear_36 : 57|1@1+ (1,0) [0|1] ""  DCDC
 SG_ P2D_CMD2_PCSOperationState_36 : 58|2@1+ (1,0) [0|3] ""  DCDC
 SG_ P2D_CMD2_DCDCLVoffControl_36 : 60|1@1+ (1,0) [0|1] ""  DCDC
 SG_ P2D_CMD2_Reserved4_36 : 61|3@1+ (1,0) [0|7] ""  DCDC

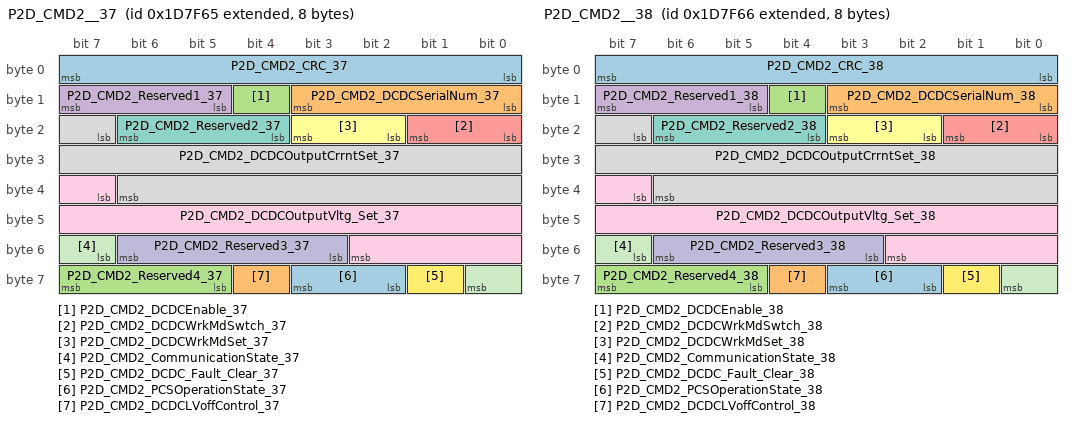
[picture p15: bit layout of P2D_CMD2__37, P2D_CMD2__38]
BO_ 2149416805 P2D_CMD2__37: 8 PC
 SG_ P2D_CMD2_CRC_37 : 0|8@1+ (1,0) [0|255] ""  DCDC
 SG_ P2D_CMD2_DCDCSerialNum_37 : 8|4@1+ (1,0) [0|15] ""  DCDC
 SG_ P2D_CMD2_DCDCEnable_37 : 12|1@1+ (1,0) [0|1] ""  DCDC
 SG_ P2D_CMD2_Reserved1_37 : 13|3@1+ (1,0) [0|7] ""  DCDC
 SG_ P2D_CMD2_DCDCWrkMdSwtch_37 : 16|2@1+ (1,0) [0|3] ""  DCDC
 SG_ P2D_CMD2_DCDCWrkMdSet_37 : 18|2@1+ (1,0) [0|3] ""  DCDC
 SG_ P2D_CMD2_Reserved2_37 : 20|3@1+ (1,0) [0|7] ""  DCDC
 SG_ P2D_CMD2_DCDCOutputCrrntSet_37 : 23|16@1+ (0.05,-2000) [-2000|1276.75] "A"  DCDC
 SG_ P2D_CMD2_DCDCOutputVltg_Set_37 : 39|12@1+ (0.1,-200) [-200|209.5] "V"  DCDC
 SG_ P2D_CMD2_Reserved3_37 : 51|4@1+ (1,0) [0|15] ""  DCDC
 SG_ P2D_CMD2_CommunicationState_37 : 55|2@1+ (1,0) [0|3] ""  DCDC
 SG_ P2D_CMD2_DCDC_Fault_Clear_37 : 57|1@1+ (1,0) [0|1] ""  DCDC
 SG_ P2D_CMD2_PCSOperationState_37 : 58|2@1+ (1,0) [0|3] ""  DCDC
 SG_ P2D_CMD2_DCDCLVoffControl_37 : 60|1@1+ (1,0) [0|1] ""  DCDC
 SG_ P2D_CMD2_Reserved4_37 : 61|3@1+ (1,0) [0|7] ""  DCDC

BO_ 2149416806 P2D_CMD2__38: 8 PC
 SG_ P2D_CMD2_CRC_38 : 0|8@1+ (1,0) [0|255] ""  DCDC
 SG_ P2D_CMD2_DCDCSerialNum_38 : 8|4@1+ (1,0) [0|15] ""  DCDC
 SG_ P2D_CMD2_DCDCEnable_38 : 12|1@1+ (1,0) [0|1] ""  DCDC
 SG_ P2D_CMD2_Reserved1_38 : 13|3@1+ (1,0) [0|7] ""  DCDC
 SG_ P2D_CMD2_DCDCWrkMdSwtch_38 : 16|2@1+ (1,0) [0|3] ""  DCDC
 SG_ P2D_CMD2_DCDCWrkMdSet_38 : 18|2@1+ (1,0) [0|3] ""  DCDC
 SG_ P2D_CMD2_Reserved2_38 : 20|3@1+ (1,0) [0|7] ""  DCDC
 SG_ P2D_CMD2_DCDCOutputCrrntSet_38 : 23|16@1+ (0.05,-2000) [-2000|1276.75] "A"  DCDC
 SG_ P2D_CMD2_DCDCOutputVltg_Set_38 : 39|12@1+ (0.1,-200) [-200|209.5] "V"  DCDC
 SG_ P2D_CMD2_Reserved3_38 : 51|4@1+ (1,0) [0|15] ""  DCDC
 SG_ P2D_CMD2_CommunicationState_38 : 55|2@1+ (1,0) [0|3] ""  DCDC
 SG_ P2D_CMD2_DCDC_Fault_Clear_38 : 57|1@1+ (1,0) [0|1] ""  DCDC
 SG_ P2D_CMD2_PCSOperationState_38 : 58|2@1+ (1,0) [0|3] ""  DCDC
 SG_ P2D_CMD2_DCDCLVoffControl_38 : 60|1@1+ (1,0) [0|1] ""  DCDC
 SG_ P2D_CMD2_Reserved4_38 : 61|3@1+ (1,0) [0|7] ""  DCDC

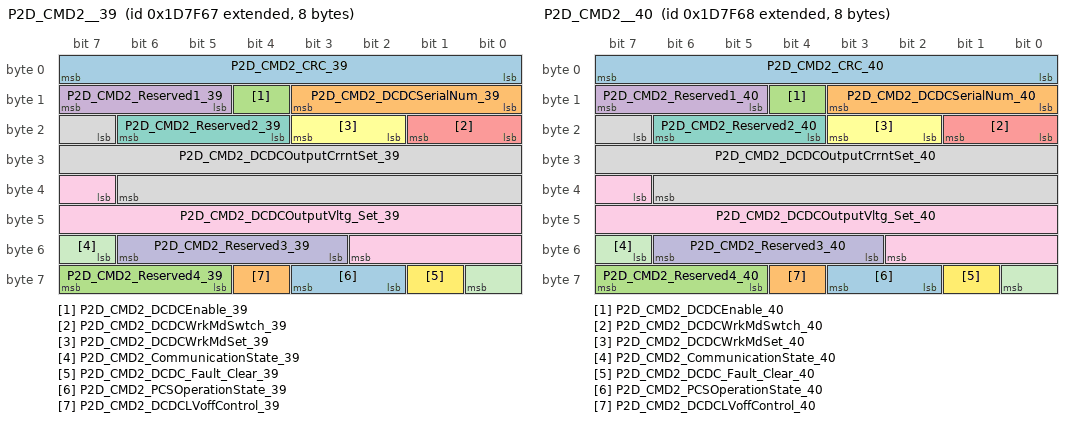
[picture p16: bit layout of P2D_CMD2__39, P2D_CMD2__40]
BO_ 2149416807 P2D_CMD2__39: 8 PC
 SG_ P2D_CMD2_CRC_39 : 0|8@1+ (1,0) [0|255] ""  DCDC
 SG_ P2D_CMD2_DCDCSerialNum_39 : 8|4@1+ (1,0) [0|15] ""  DCDC
 SG_ P2D_CMD2_DCDCEnable_39 : 12|1@1+ (1,0) [0|1] ""  DCDC
 SG_ P2D_CMD2_Reserved1_39 : 13|3@1+ (1,0) [0|7] ""  DCDC
 SG_ P2D_CMD2_DCDCWrkMdSwtch_39 : 16|2@1+ (1,0) [0|3] ""  DCDC
 SG_ P2D_CMD2_DCDCWrkMdSet_39 : 18|2@1+ (1,0) [0|3] ""  DCDC
 SG_ P2D_CMD2_Reserved2_39 : 20|3@1+ (1,0) [0|7] ""  DCDC
 SG_ P2D_CMD2_DCDCOutputCrrntSet_39 : 23|16@1+ (0.05,-2000) [-2000|1276.75] "A"  DCDC
 SG_ P2D_CMD2_DCDCOutputVltg_Set_39 : 39|12@1+ (0.1,-200) [-200|209.5] "V"  DCDC
 SG_ P2D_CMD2_Reserved3_39 : 51|4@1+ (1,0) [0|15] ""  DCDC
 SG_ P2D_CMD2_CommunicationState_39 : 55|2@1+ (1,0) [0|3] ""  DCDC
 SG_ P2D_CMD2_DCDC_Fault_Clear_39 : 57|1@1+ (1,0) [0|1] ""  DCDC
 SG_ P2D_CMD2_PCSOperationState_39 : 58|2@1+ (1,0) [0|3] ""  DCDC
 SG_ P2D_CMD2_DCDCLVoffControl_39 : 60|1@1+ (1,0) [0|1] ""  DCDC
 SG_ P2D_CMD2_Reserved4_39 : 61|3@1+ (1,0) [0|7] ""  DCDC

BO_ 2149416808 P2D_CMD2__40: 8 PC
 SG_ P2D_CMD2_CRC_40 : 0|8@1+ (1,0) [0|255] ""  DCDC
 SG_ P2D_CMD2_DCDCSerialNum_40 : 8|4@1+ (1,0) [0|15] ""  DCDC
 SG_ P2D_CMD2_DCDCEnable_40 : 12|1@1+ (1,0) [0|1] ""  DCDC
 SG_ P2D_CMD2_Reserved1_40 : 13|3@1+ (1,0) [0|7] ""  DCDC
 SG_ P2D_CMD2_DCDCWrkMdSwtch_40 : 16|2@1+ (1,0) [0|3] ""  DCDC
 SG_ P2D_CMD2_DCDCWrkMdSet_40 : 18|2@1+ (1,0) [0|3] ""  DCDC
 SG_ P2D_CMD2_Reserved2_40 : 20|3@1+ (1,0) [0|7] ""  DCDC
 SG_ P2D_CMD2_DCDCOutputCrrntSet_40 : 23|16@1+ (0.05,-2000) [-2000|1276.75] "A"  DCDC
 SG_ P2D_CMD2_DCDCOutputVltg_Set_40 : 39|12@1+ (0.1,-200) [-200|209.5] "V"  DCDC
 SG_ P2D_CMD2_Reserved3_40 : 51|4@1+ (1,0) [0|15] ""  DCDC
 SG_ P2D_CMD2_CommunicationState_40 : 55|2@1+ (1,0) [0|3] ""  DCDC
 SG_ P2D_CMD2_DCDC_Fault_Clear_40 : 57|1@1+ (1,0) [0|1] ""  DCDC
 SG_ P2D_CMD2_PCSOperationState_40 : 58|2@1+ (1,0) [0|3] ""  DCDC
 SG_ P2D_CMD2_DCDCLVoffControl_40 : 60|1@1+ (1,0) [0|1] ""  DCDC
 SG_ P2D_CMD2_Reserved4_40 : 61|3@1+ (1,0) [0|7] ""  DCDC

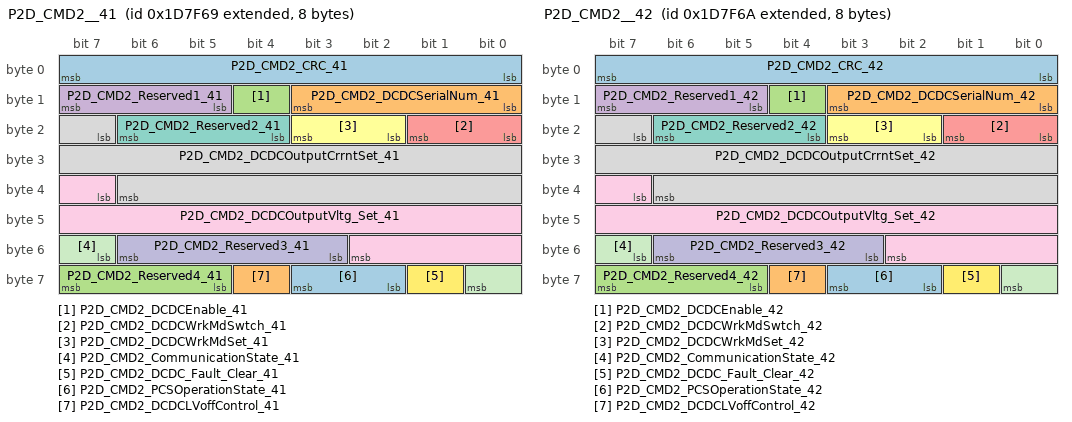
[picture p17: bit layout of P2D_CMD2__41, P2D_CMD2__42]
BO_ 2149416809 P2D_CMD2__41: 8 PC
 SG_ P2D_CMD2_CRC_41 : 0|8@1+ (1,0) [0|255] ""  DCDC
 SG_ P2D_CMD2_DCDCSerialNum_41 : 8|4@1+ (1,0) [0|15] ""  DCDC
 SG_ P2D_CMD2_DCDCEnable_41 : 12|1@1+ (1,0) [0|1] ""  DCDC
 SG_ P2D_CMD2_Reserved1_41 : 13|3@1+ (1,0) [0|7] ""  DCDC
 SG_ P2D_CMD2_DCDCWrkMdSwtch_41 : 16|2@1+ (1,0) [0|3] ""  DCDC
 SG_ P2D_CMD2_DCDCWrkMdSet_41 : 18|2@1+ (1,0) [0|3] ""  DCDC
 SG_ P2D_CMD2_Reserved2_41 : 20|3@1+ (1,0) [0|7] ""  DCDC
 SG_ P2D_CMD2_DCDCOutputCrrntSet_41 : 23|16@1+ (0.05,-2000) [-2000|1276.75] "A"  DCDC
 SG_ P2D_CMD2_DCDCOutputVltg_Set_41 : 39|12@1+ (0.1,-200) [-200|209.5] "V"  DCDC
 SG_ P2D_CMD2_Reserved3_41 : 51|4@1+ (1,0) [0|15] ""  DCDC
 SG_ P2D_CMD2_CommunicationState_41 : 55|2@1+ (1,0) [0|3] ""  DCDC
 SG_ P2D_CMD2_DCDC_Fault_Clear_41 : 57|1@1+ (1,0) [0|1] ""  DCDC
 SG_ P2D_CMD2_PCSOperationState_41 : 58|2@1+ (1,0) [0|3] ""  DCDC
 SG_ P2D_CMD2_DCDCLVoffControl_41 : 60|1@1+ (1,0) [0|1] ""  DCDC
 SG_ P2D_CMD2_Reserved4_41 : 61|3@1+ (1,0) [0|7] ""  DCDC

BO_ 2149416810 P2D_CMD2__42: 8 PC
 SG_ P2D_CMD2_CRC_42 : 0|8@1+ (1,0) [0|255] ""  DCDC
 SG_ P2D_CMD2_DCDCSerialNum_42 : 8|4@1+ (1,0) [0|15] ""  DCDC
 SG_ P2D_CMD2_DCDCEnable_42 : 12|1@1+ (1,0) [0|1] ""  DCDC
 SG_ P2D_CMD2_Reserved1_42 : 13|3@1+ (1,0) [0|7] ""  DCDC
 SG_ P2D_CMD2_DCDCWrkMdSwtch_42 : 16|2@1+ (1,0) [0|3] ""  DCDC
 SG_ P2D_CMD2_DCDCWrkMdSet_42 : 18|2@1+ (1,0) [0|3] ""  DCDC
 SG_ P2D_CMD2_Reserved2_42 : 20|3@1+ (1,0) [0|7] ""  DCDC
 SG_ P2D_CMD2_DCDCOutputCrrntSet_42 : 23|16@1+ (0.05,-2000) [-2000|1276.75] "A"  DCDC
 SG_ P2D_CMD2_DCDCOutputVltg_Set_42 : 39|12@1+ (0.1,-200) [-200|209.5] "V"  DCDC
 SG_ P2D_CMD2_Reserved3_42 : 51|4@1+ (1,0) [0|15] ""  DCDC
 SG_ P2D_CMD2_CommunicationState_42 : 55|2@1+ (1,0) [0|3] ""  DCDC
 SG_ P2D_CMD2_DCDC_Fault_Clear_42 : 57|1@1+ (1,0) [0|1] ""  DCDC
 SG_ P2D_CMD2_PCSOperationState_42 : 58|2@1+ (1,0) [0|3] ""  DCDC
 SG_ P2D_CMD2_DCDCLVoffControl_42 : 60|1@1+ (1,0) [0|1] ""  DCDC
 SG_ P2D_CMD2_Reserved4_42 : 61|3@1+ (1,0) [0|7] ""  DCDC

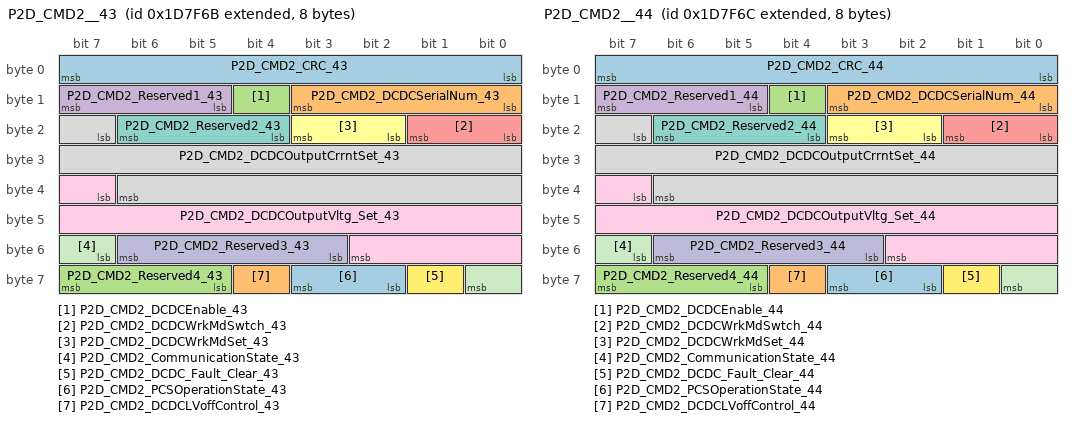
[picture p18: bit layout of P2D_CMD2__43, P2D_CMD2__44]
BO_ 2149416811 P2D_CMD2__43: 8 PC
 SG_ P2D_CMD2_CRC_43 : 0|8@1+ (1,0) [0|255] ""  DCDC
 SG_ P2D_CMD2_DCDCSerialNum_43 : 8|4@1+ (1,0) [0|15] ""  DCDC
 SG_ P2D_CMD2_DCDCEnable_43 : 12|1@1+ (1,0) [0|1] ""  DCDC
 SG_ P2D_CMD2_Reserved1_43 : 13|3@1+ (1,0) [0|7] ""  DCDC
 SG_ P2D_CMD2_DCDCWrkMdSwtch_43 : 16|2@1+ (1,0) [0|3] ""  DCDC
 SG_ P2D_CMD2_DCDCWrkMdSet_43 : 18|2@1+ (1,0) [0|3] ""  DCDC
 SG_ P2D_CMD2_Reserved2_43 : 20|3@1+ (1,0) [0|7] ""  DCDC
 SG_ P2D_CMD2_DCDCOutputCrrntSet_43 : 23|16@1+ (0.05,-2000) [-2000|1276.75] "A"  DCDC
 SG_ P2D_CMD2_DCDCOutputVltg_Set_43 : 39|12@1+ (0.1,-200) [-200|209.5] "V"  DCDC
 SG_ P2D_CMD2_Reserved3_43 : 51|4@1+ (1,0) [0|15] ""  DCDC
 SG_ P2D_CMD2_CommunicationState_43 : 55|2@1+ (1,0) [0|3] ""  DCDC
 SG_ P2D_CMD2_DCDC_Fault_Clear_43 : 57|1@1+ (1,0) [0|1] ""  DCDC
 SG_ P2D_CMD2_PCSOperationState_43 : 58|2@1+ (1,0) [0|3] ""  DCDC
 SG_ P2D_CMD2_DCDCLVoffControl_43 : 60|1@1+ (1,0) [0|1] ""  DCDC
 SG_ P2D_CMD2_Reserved4_43 : 61|3@1+ (1,0) [0|7] ""  DCDC

BO_ 2149416812 P2D_CMD2__44: 8 PC
 SG_ P2D_CMD2_CRC_44 : 0|8@1+ (1,0) [0|255] ""  DCDC
 SG_ P2D_CMD2_DCDCSerialNum_44 : 8|4@1+ (1,0) [0|15] ""  DCDC
 SG_ P2D_CMD2_DCDCEnable_44 : 12|1@1+ (1,0) [0|1] ""  DCDC
 SG_ P2D_CMD2_Reserved1_44 : 13|3@1+ (1,0) [0|7] ""  DCDC
 SG_ P2D_CMD2_DCDCWrkMdSwtch_44 : 16|2@1+ (1,0) [0|3] ""  DCDC
 SG_ P2D_CMD2_DCDCWrkMdSet_44 : 18|2@1+ (1,0) [0|3] ""  DCDC
 SG_ P2D_CMD2_Reserved2_44 : 20|3@1+ (1,0) [0|7] ""  DCDC
 SG_ P2D_CMD2_DCDCOutputCrrntSet_44 : 23|16@1+ (0.05,-2000) [-2000|1276.75] "A"  DCDC
 SG_ P2D_CMD2_DCDCOutputVltg_Set_44 : 39|12@1+ (0.1,-200) [-200|209.5] "V"  DCDC
 SG_ P2D_CMD2_Reserved3_44 : 51|4@1+ (1,0) [0|15] ""  DCDC
 SG_ P2D_CMD2_CommunicationState_44 : 55|2@1+ (1,0) [0|3] ""  DCDC
 SG_ P2D_CMD2_DCDC_Fault_Clear_44 : 57|1@1+ (1,0) [0|1] ""  DCDC
 SG_ P2D_CMD2_PCSOperationState_44 : 58|2@1+ (1,0) [0|3] ""  DCDC
 SG_ P2D_CMD2_DCDCLVoffControl_44 : 60|1@1+ (1,0) [0|1] ""  DCDC
 SG_ P2D_CMD2_Reserved4_44 : 61|3@1+ (1,0) [0|7] ""  DCDC

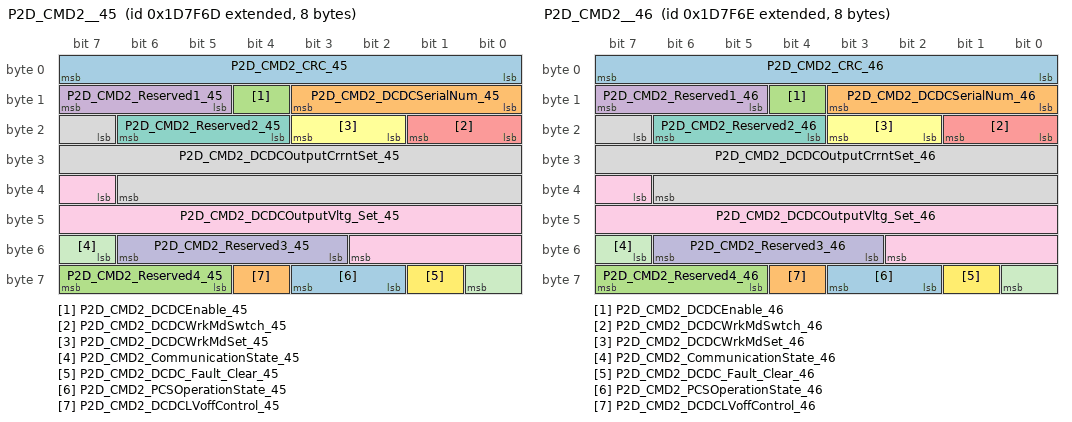
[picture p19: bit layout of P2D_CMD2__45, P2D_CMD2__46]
BO_ 2149416813 P2D_CMD2__45: 8 PC
 SG_ P2D_CMD2_CRC_45 : 0|8@1+ (1,0) [0|255] ""  DCDC
 SG_ P2D_CMD2_DCDCSerialNum_45 : 8|4@1+ (1,0) [0|15] ""  DCDC
 SG_ P2D_CMD2_DCDCEnable_45 : 12|1@1+ (1,0) [0|1] ""  DCDC
 SG_ P2D_CMD2_Reserved1_45 : 13|3@1+ (1,0) [0|7] ""  DCDC
 SG_ P2D_CMD2_DCDCWrkMdSwtch_45 : 16|2@1+ (1,0) [0|3] ""  DCDC
 SG_ P2D_CMD2_DCDCWrkMdSet_45 : 18|2@1+ (1,0) [0|3] ""  DCDC
 SG_ P2D_CMD2_Reserved2_45 : 20|3@1+ (1,0) [0|7] ""  DCDC
 SG_ P2D_CMD2_DCDCOutputCrrntSet_45 : 23|16@1+ (0.05,-2000) [-2000|1276.75] "A"  DCDC
 SG_ P2D_CMD2_DCDCOutputVltg_Set_45 : 39|12@1+ (0.1,-200) [-200|209.5] "V"  DCDC
 SG_ P2D_CMD2_Reserved3_45 : 51|4@1+ (1,0) [0|15] ""  DCDC
 SG_ P2D_CMD2_CommunicationState_45 : 55|2@1+ (1,0) [0|3] ""  DCDC
 SG_ P2D_CMD2_DCDC_Fault_Clear_45 : 57|1@1+ (1,0) [0|1] ""  DCDC
 SG_ P2D_CMD2_PCSOperationState_45 : 58|2@1+ (1,0) [0|3] ""  DCDC
 SG_ P2D_CMD2_DCDCLVoffControl_45 : 60|1@1+ (1,0) [0|1] ""  DCDC
 SG_ P2D_CMD2_Reserved4_45 : 61|3@1+ (1,0) [0|7] ""  DCDC

BO_ 2149416814 P2D_CMD2__46: 8 PC
 SG_ P2D_CMD2_CRC_46 : 0|8@1+ (1,0) [0|255] ""  DCDC
 SG_ P2D_CMD2_DCDCSerialNum_46 : 8|4@1+ (1,0) [0|15] ""  DCDC
 SG_ P2D_CMD2_DCDCEnable_46 : 12|1@1+ (1,0) [0|1] ""  DCDC
 SG_ P2D_CMD2_Reserved1_46 : 13|3@1+ (1,0) [0|7] ""  DCDC
 SG_ P2D_CMD2_DCDCWrkMdSwtch_46 : 16|2@1+ (1,0) [0|3] ""  DCDC
 SG_ P2D_CMD2_DCDCWrkMdSet_46 : 18|2@1+ (1,0) [0|3] ""  DCDC
 SG_ P2D_CMD2_Reserved2_46 : 20|3@1+ (1,0) [0|7] ""  DCDC
 SG_ P2D_CMD2_DCDCOutputCrrntSet_46 : 23|16@1+ (0.05,-2000) [-2000|1276.75] "A"  DCDC
 SG_ P2D_CMD2_DCDCOutputVltg_Set_46 : 39|12@1+ (0.1,-200) [-200|209.5] "V"  DCDC
 SG_ P2D_CMD2_Reserved3_46 : 51|4@1+ (1,0) [0|15] ""  DCDC
 SG_ P2D_CMD2_CommunicationState_46 : 55|2@1+ (1,0) [0|3] ""  DCDC
 SG_ P2D_CMD2_DCDC_Fault_Clear_46 : 57|1@1+ (1,0) [0|1] ""  DCDC
 SG_ P2D_CMD2_PCSOperationState_46 : 58|2@1+ (1,0) [0|3] ""  DCDC
 SG_ P2D_CMD2_DCDCLVoffControl_46 : 60|1@1+ (1,0) [0|1] ""  DCDC
 SG_ P2D_CMD2_Reserved4_46 : 61|3@1+ (1,0) [0|7] ""  DCDC

BO_ 2149416815 P2D_CMD2__47: 8 PC
 SG_ P2D_CMD2_CRC_47 : 0|8@1+ (1,0) [0|255] ""  DCDC
 SG_ P2D_CMD2_DCDCSerialNum_47 : 8|4@1+ (1,0) [0|15] ""  DCDC
 SG_ P2D_CMD2_DCDCEnable_47 : 12|1@1+ (1,0) [0|1] ""  DCDC
 SG_ P2D_CMD2_Reserved1_47 : 13|3@1+ (1,0) [0|7] ""  DCDC
 SG_ P2D_CMD2_DCDCWrkMdSwtch_47 : 16|2@1+ (1,0) [0|3] ""  DCDC
 SG_ P2D_CMD2_DCDCWrkMdSet_47 : 18|2@1+ (1,0) [0|3] ""  DCDC
 SG_ P2D_CMD2_Reserved2_47 : 20|3@1+ (1,0) [0|7] ""  DCDC
 SG_ P2D_CMD2_DCDCOutputCrrntSet_47 : 23|16@1+ (0.05,-2000) [-2000|1276.75] "A"  DCDC
 SG_ P2D_CMD2_DCDCOutputVltg_Set_47 : 39|12@1+ (0.1,-200) [-200|209.5] "V"  DCDC
 SG_ P2D_CMD2_Reserved3_47 : 51|4@1+ (1,0) [0|15] ""  DCDC
 SG_ P2D_CMD2_CommunicationState_47 : 55|2@1+ (1,0) [0|3] ""  DCDC
 SG_ P2D_CMD2_DCDC_Fault_Clear_47 : 57|1@1+ (1,0) [0|1] ""  DCDC
 SG_ P2D_CMD2_PCSOperationState_47 : 58|2@1+ (1,0) [0|3] ""  DCDC
 SG_ P2D_CMD2_DCDCLVoffControl_47 : 60|1@1+ (1,0) [0|1] ""  DCDC
 SG_ P2D_CMD2_Reserved4_47 : 61|3@1+ (1,0) [0|7] ""  DCDC

BO_ 2149416816 P2D_CMD2__48: 8 PC
 SG_ P2D_CMD2_CRC_48 : 0|8@1+ (1,0) [0|255] ""  DCDC
 SG_ P2D_CMD2_DCDCSerialNum_48 : 8|4@1+ (1,0) [0|15] ""  DCDC
 SG_ P2D_CMD2_DCDCEnable_48 : 12|1@1+ (1,0) [0|1] ""  DCDC
 SG_ P2D_CMD2_Reserved1_48 : 13|3@1+ (1,0) [0|7] ""  DCDC
 SG_ P2D_CMD2_DCDCWrkMdSwtch_48 : 16|2@1+ (1,0) [0|3] ""  DCDC
 SG_ P2D_CMD2_DCDCWrkMdSet_48 : 18|2@1+ (1,0) [0|3] ""  DCDC
 SG_ P2D_CMD2_Reserved2_48 : 20|3@1+ (1,0) [0|7] ""  DCDC
 SG_ P2D_CMD2_DCDCOutputCrrntSet_48 : 23|16@1+ (0.05,-2000) [-2000|1276.75] "A"  DCDC
 SG_ P2D_CMD2_DCDCOutputVltg_Set_48 : 39|12@1+ (0.1,-200) [-200|209.5] "V"  DCDC
 SG_ P2D_CMD2_Reserved3_48 : 51|4@1+ (1,0) [0|15] ""  DCDC
 SG_ P2D_CMD2_CommunicationState_48 : 55|2@1+ (1,0) [0|3] ""  DCDC
 SG_ P2D_CMD2_DCDC_Fault_Clear_48 : 57|1@1+ (1,0) [0|1] ""  DCDC
 SG_ P2D_CMD2_PCSOperationState_48 : 58|2@1+ (1,0) [0|3] ""  DCDC
 SG_ P2D_CMD2_DCDCLVoffControl_48 : 60|1@1+ (1,0) [0|1] ""  DCDC
 SG_ P2D_CMD2_Reserved4_48 : 61|3@1+ (1,0) [0|7] ""  DCDC

BO_ 2149416817 P2D_CMD2__49: 8 PC
 SG_ P2D_CMD2_CRC_49 : 0|8@1+ (1,0) [0|255] ""  DCDC
 SG_ P2D_CMD2_DCDCSerialNum_49 : 8|4@1+ (1,0) [0|15] ""  DCDC
 SG_ P2D_CMD2_DCDCEnable_49 : 12|1@1+ (1,0) [0|1] ""  DCDC
 SG_ P2D_CMD2_Reserved1_49 : 13|3@1+ (1,0) [0|7] ""  DCDC
 SG_ P2D_CMD2_DCDCWrkMdSwtch_49 : 16|2@1+ (1,0) [0|3] ""  DCDC
 SG_ P2D_CMD2_DCDCWrkMdSet_49 : 18|2@1+ (1,0) [0|3] ""  DCDC
 SG_ P2D_CMD2_Reserved2_49 : 20|3@1+ (1,0) [0|7] ""  DCDC
 SG_ P2D_CMD2_DCDCOutputCrrntSet_49 : 23|16@1+ (0.05,-2000) [-2000|1276.75] "A"  DCDC
 SG_ P2D_CMD2_DCDCOutputVltg_Set_49 : 39|12@1+ (0.1,-200) [-200|209.5] "V"  DCDC
 SG_ P2D_CMD2_Reserved3_49 : 51|4@1+ (1,0) [0|15] ""  DCDC
 SG_ P2D_CMD2_CommunicationState_49 : 55|2@1+ (1,0) [0|3] ""  DCDC
 SG_ P2D_CMD2_DCDC_Fault_Clear_49 : 57|1@1+ (1,0) [0|1] ""  DCDC
 SG_ P2D_CMD2_PCSOperationState_49 : 58|2@1+ (1,0) [0|3] ""  DCDC
 SG_ P2D_CMD2_DCDCLVoffControl_49 : 60|1@1+ (1,0) [0|1] ""  DCDC
 SG_ P2D_CMD2_Reserved4_49 : 61|3@1+ (1,0) [0|7] ""  DCDC

BO_ 2149416818 P2D_CMD2__50: 8 PC
 SG_ P2D_CMD2_CRC_50 : 0|8@1+ (1,0) [0|255] ""  DCDC
 SG_ P2D_CMD2_DCDCSerialNum_50 : 8|4@1+ (1,0) [0|15] ""  DCDC
 SG_ P2D_CMD2_DCDCEnable_50 : 12|1@1+ (1,0) [0|1] ""  DCDC
 SG_ P2D_CMD2_Reserved1_50 : 13|3@1+ (1,0) [0|7] ""  DCDC
 SG_ P2D_CMD2_DCDCWrkMdSwtch_50 : 16|2@1+ (1,0) [0|3] ""  DCDC
 SG_ P2D_CMD2_DCDCWrkMdSet_50 : 18|2@1+ (1,0) [0|3] ""  DCDC
 SG_ P2D_CMD2_Reserved2_50 : 20|3@1+ (1,0) [0|7] ""  DCDC
 SG_ P2D_CMD2_DCDCOutputCrrntSet_50 : 23|16@1+ (0.05,-2000) [-2000|1276.75] "A"  DCDC
 SG_ P2D_CMD2_DCDCOutputVltg_Set_50 : 39|12@1+ (0.1,-200) [-200|209.5] "V"  DCDC
 SG_ P2D_CMD2_Reserved3_50 : 51|4@1+ (1,0) [0|15] ""  DCDC
 SG_ P2D_CMD2_CommunicationState_50 : 55|2@1+ (1,0) [0|3] ""  DCDC
 SG_ P2D_CMD2_DCDC_Fault_Clear_50 : 57|1@1+ (1,0) [0|1] ""  DCDC
 SG_ P2D_CMD2_PCSOperationState_50 : 58|2@1+ (1,0) [0|3] ""  DCDC
 SG_ P2D_CMD2_DCDCLVoffControl_50 : 60|1@1+ (1,0) [0|1] ""  DCDC
 SG_ P2D_CMD2_Reserved4_50 : 61|3@1+ (1,0) [0|7] ""  DCDC

BO_ 2149416819 P2D_CMD2__51: 8 PC
 SG_ P2D_CMD2_CRC_51 : 0|8@1+ (1,0) [0|255] ""  DCDC
 SG_ P2D_CMD2_DCDCSerialNum_51 : 8|4@1+ (1,0) [0|15] ""  DCDC
 SG_ P2D_CMD2_DCDCEnable_51 : 12|1@1+ (1,0) [0|1] ""  DCDC
 SG_ P2D_CMD2_Reserved1_51 : 13|3@1+ (1,0) [0|7] ""  DCDC
 SG_ P2D_CMD2_DCDCWrkMdSwtch_51 : 16|2@1+ (1,0) [0|3] ""  DCDC
 SG_ P2D_CMD2_DCDCWrkMdSet_51 : 18|2@1+ (1,0) [0|3] ""  DCDC
 SG_ P2D_CMD2_Reserved2_51 : 20|3@1+ (1,0) [0|7] ""  DCDC
 SG_ P2D_CMD2_DCDCOutputCrrntSet_51 : 23|16@1+ (0.05,-2000) [-2000|1276.75] "A"  DCDC
 SG_ P2D_CMD2_DCDCOutputVltg_Set_51 : 39|12@1+ (0.1,-200) [-200|209.5] "V"  DCDC
 SG_ P2D_CMD2_Reserved3_51 : 51|4@1+ (1,0) [0|15] ""  DCDC
 SG_ P2D_CMD2_CommunicationState_51 : 55|2@1+ (1,0) [0|3] ""  DCDC
 SG_ P2D_CMD2_DCDC_Fault_Clear_51 : 57|1@1+ (1,0) [0|1] ""  DCDC
 SG_ P2D_CMD2_PCSOperationState_51 : 58|2@1+ (1,0) [0|3] ""  DCDC
 SG_ P2D_CMD2_DCDCLVoffControl_51 : 60|1@1+ (1,0) [0|1] ""  DCDC
 SG_ P2D_CMD2_Reserved4_51 : 61|3@1+ (1,0) [0|7] ""  DCDC

BO_ 2149416820 P2D_CMD2__52: 8 PC
 SG_ P2D_CMD2_CRC_52 : 0|8@1+ (1,0) [0|255] ""  DCDC
 SG_ P2D_CMD2_DCDCSerialNum_52 : 8|4@1+ (1,0) [0|15] ""  DCDC
 SG_ P2D_CMD2_DCDCEnable_52 : 12|1@1+ (1,0) [0|1] ""  DCDC
 SG_ P2D_CMD2_Reserved1_52 : 13|3@1+ (1,0) [0|7] ""  DCDC
 SG_ P2D_CMD2_DCDCWrkMdSwtch_52 : 16|2@1+ (1,0) [0|3] ""  DCDC
 SG_ P2D_CMD2_DCDCWrkMdSet_52 : 18|2@1+ (1,0) [0|3] ""  DCDC
 SG_ P2D_CMD2_Reserved2_52 : 20|3@1+ (1,0) [0|7] ""  DCDC
 SG_ P2D_CMD2_DCDCOutputCrrntSet_52 : 23|16@1+ (0.05,-2000) [-2000|1276.75] "A"  DCDC
 SG_ P2D_CMD2_DCDCOutputVltg_Set_52 : 39|12@1+ (0.1,-200) [-200|209.5] "V"  DCDC
 SG_ P2D_CMD2_Reserved3_52 : 51|4@1+ (1,0) [0|15] ""  DCDC
 SG_ P2D_CMD2_CommunicationState_52 : 55|2@1+ (1,0) [0|3] ""  DCDC
 SG_ P2D_CMD2_DCDC_Fault_Clear_52 : 57|1@1+ (1,0) [0|1] ""  DCDC
 SG_ P2D_CMD2_PCSOperationState_52 : 58|2@1+ (1,0) [0|3] ""  DCDC
 SG_ P2D_CMD2_DCDCLVoffControl_52 : 60|1@1+ (1,0) [0|1] ""  DCDC
 SG_ P2D_CMD2_Reserved4_52 : 61|3@1+ (1,0) [0|7] ""  DCDC

BO_ 2149416821 P2D_CMD2__53: 8 PC
 SG_ P2D_CMD2_CRC_53 : 0|8@1+ (1,0) [0|255] ""  DCDC
 SG_ P2D_CMD2_DCDCSerialNum_53 : 8|4@1+ (1,0) [0|15] ""  DCDC
 SG_ P2D_CMD2_DCDCEnable_53 : 12|1@1+ (1,0) [0|1] ""  DCDC
 SG_ P2D_CMD2_Reserved1_53 : 13|3@1+ (1,0) [0|7] ""  DCDC
 SG_ P2D_CMD2_DCDCWrkMdSwtch_53 : 16|2@1+ (1,0) [0|3] ""  DCDC
 SG_ P2D_CMD2_DCDCWrkMdSet_53 : 18|2@1+ (1,0) [0|3] ""  DCDC
 SG_ P2D_CMD2_Reserved2_53 : 20|3@1+ (1,0) [0|7] ""  DCDC
 SG_ P2D_CMD2_DCDCOutputCrrntSet_53 : 23|16@1+ (0.05,-2000) [-2000|1276.75] "A"  DCDC
 SG_ P2D_CMD2_DCDCOutputVltg_Set_53 : 39|12@1+ (0.1,-200) [-200|209.5] "V"  DCDC
 SG_ P2D_CMD2_Reserved3_53 : 51|4@1+ (1,0) [0|15] ""  DCDC
 SG_ P2D_CMD2_CommunicationState_53 : 55|2@1+ (1,0) [0|3] ""  DCDC
 SG_ P2D_CMD2_DCDC_Fault_Clear_53 : 57|1@1+ (1,0) [0|1] ""  DCDC
 SG_ P2D_CMD2_PCSOperationState_53 : 58|2@1+ (1,0) [0|3] ""  DCDC
 SG_ P2D_CMD2_DCDCLVoffControl_53 : 60|1@1+ (1,0) [0|1] ""  DCDC
 SG_ P2D_CMD2_Reserved4_53 : 61|3@1+ (1,0) [0|7] ""  DCDC

BO_ 2149416822 P2D_CMD2__54: 8 PC
 SG_ P2D_CMD2_CRC_54 : 0|8@1+ (1,0) [0|255] ""  DCDC
 SG_ P2D_CMD2_DCDCSerialNum_54 : 8|4@1+ (1,0) [0|15] ""  DCDC
 SG_ P2D_CMD2_DCDCEnable_54 : 12|1@1+ (1,0) [0|1] ""  DCDC
 SG_ P2D_CMD2_Reserved1_54 : 13|3@1+ (1,0) [0|7] ""  DCDC
 SG_ P2D_CMD2_DCDCWrkMdSwtch_54 : 16|2@1+ (1,0) [0|3] ""  DCDC
 SG_ P2D_CMD2_DCDCWrkMdSet_54 : 18|2@1+ (1,0) [0|3] ""  DCDC
 SG_ P2D_CMD2_Reserved2_54 : 20|3@1+ (1,0) [0|7] ""  DCDC
 SG_ P2D_CMD2_DCDCOutputCrrntSet_54 : 23|16@1+ (0.05,-2000) [-2000|1276.75] "A"  DCDC
 SG_ P2D_CMD2_DCDCOutputVltg_Set_54 : 39|12@1+ (0.1,-200) [-200|209.5] "V"  DCDC
 SG_ P2D_CMD2_Reserved3_54 : 51|4@1+ (1,0) [0|15] ""  DCDC
 SG_ P2D_CMD2_CommunicationState_54 : 55|2@1+ (1,0) [0|3] ""  DCDC
 SG_ P2D_CMD2_DCDC_Fault_Clear_54 : 57|1@1+ (1,0) [0|1] ""  DCDC
 SG_ P2D_CMD2_PCSOperationState_54 : 58|2@1+ (1,0) [0|3] ""  DCDC
 SG_ P2D_CMD2_DCDCLVoffControl_54 : 60|1@1+ (1,0) [0|1] ""  DCDC
 SG_ P2D_CMD2_Reserved4_54 : 61|3@1+ (1,0) [0|7] ""  DCDC

BO_ 2149416823 P2D_CMD2__55: 8 PC
 SG_ P2D_CMD2_CRC_55 : 0|8@1+ (1,0) [0|255] ""  DCDC
 SG_ P2D_CMD2_DCDCSerialNum_55 : 8|4@1+ (1,0) [0|15] ""  DCDC
 SG_ P2D_CMD2_DCDCEnable_55 : 12|1@1+ (1,0) [0|1] ""  DCDC
 SG_ P2D_CMD2_Reserved1_55 : 13|3@1+ (1,0) [0|7] ""  DCDC
 SG_ P2D_CMD2_DCDCWrkMdSwtch_55 : 16|2@1+ (1,0) [0|3] ""  DCDC
 SG_ P2D_CMD2_DCDCWrkMdSet_55 : 18|2@1+ (1,0) [0|3] ""  DCDC
 SG_ P2D_CMD2_Reserved2_55 : 20|3@1+ (1,0) [0|7] ""  DCDC
 SG_ P2D_CMD2_DCDCOutputCrrntSet_55 : 23|16@1+ (0.05,-2000) [-2000|1276.75] "A"  DCDC
 SG_ P2D_CMD2_DCDCOutputVltg_Set_55 : 39|12@1+ (0.1,-200) [-200|209.5] "V"  DCDC
 SG_ P2D_CMD2_Reserved3_55 : 51|4@1+ (1,0) [0|15] ""  DCDC
 SG_ P2D_CMD2_CommunicationState_55 : 55|2@1+ (1,0) [0|3] ""  DCDC
 SG_ P2D_CMD2_DCDC_Fault_Clear_55 : 57|1@1+ (1,0) [0|1] ""  DCDC
 SG_ P2D_CMD2_PCSOperationState_55 : 58|2@1+ (1,0) [0|3] ""  DCDC
 SG_ P2D_CMD2_DCDCLVoffControl_55 : 60|1@1+ (1,0) [0|1] ""  DCDC
 SG_ P2D_CMD2_Reserved4_55 : 61|3@1+ (1,0) [0|7] ""  DCDC

BO_ 2149416824 P2D_CMD2__56: 8 PC
 SG_ P2D_CMD2_CRC_56 : 0|8@1+ (1,0) [0|255] ""  DCDC
 SG_ P2D_CMD2_DCDCSerialNum_56 : 8|4@1+ (1,0) [0|15] ""  DCDC
 SG_ P2D_CMD2_DCDCEnable_56 : 12|1@1+ (1,0) [0|1] ""  DCDC
 SG_ P2D_CMD2_Reserved1_56 : 13|3@1+ (1,0) [0|7] ""  DCDC
 SG_ P2D_CMD2_DCDCWrkMdSwtch_56 : 16|2@1+ (1,0) [0|3] ""  DCDC
 SG_ P2D_CMD2_DCDCWrkMdSet_56 : 18|2@1+ (1,0) [0|3] ""  DCDC
 SG_ P2D_CMD2_Reserved2_56 : 20|3@1+ (1,0) [0|7] ""  DCDC
 SG_ P2D_CMD2_DCDCOutputCrrntSet_56 : 23|16@1+ (0.05,-2000) [-2000|1276.75] "A"  DCDC
 SG_ P2D_CMD2_DCDCOutputVltg_Set_56 : 39|12@1+ (0.1,-200) [-200|209.5] "V"  DCDC
 SG_ P2D_CMD2_Reserved3_56 : 51|4@1+ (1,0) [0|15] ""  DCDC
 SG_ P2D_CMD2_CommunicationState_56 : 55|2@1+ (1,0) [0|3] ""  DCDC
 SG_ P2D_CMD2_DCDC_Fault_Clear_56 : 57|1@1+ (1,0) [0|1] ""  DCDC
 SG_ P2D_CMD2_PCSOperationState_56 : 58|2@1+ (1,0) [0|3] ""  DCDC
 SG_ P2D_CMD2_DCDCLVoffControl_56 : 60|1@1+ (1,0) [0|1] ""  DCDC
 SG_ P2D_CMD2_Reserved4_56 : 61|3@1+ (1,0) [0|7] ""  DCDC

BO_ 2149416825 P2D_CMD2__57: 8 PC
 SG_ P2D_CMD2_CRC_57 : 0|8@1+ (1,0) [0|255] ""  DCDC
 SG_ P2D_CMD2_DCDCSerialNum_57 : 8|4@1+ (1,0) [0|15] ""  DCDC
 SG_ P2D_CMD2_DCDCEnable_57 : 12|1@1+ (1,0) [0|1] ""  DCDC
 SG_ P2D_CMD2_Reserved1_57 : 13|3@1+ (1,0) [0|7] ""  DCDC
 SG_ P2D_CMD2_DCDCWrkMdSwtch_57 : 16|2@1+ (1,0) [0|3] ""  DCDC
 SG_ P2D_CMD2_DCDCWrkMdSet_57 : 18|2@1+ (1,0) [0|3] ""  DCDC
 SG_ P2D_CMD2_Reserved2_57 : 20|3@1+ (1,0) [0|7] ""  DCDC
 SG_ P2D_CMD2_DCDCOutputCrrntSet_57 : 23|16@1+ (0.05,-2000) [-2000|1276.75] "A"  DCDC
 SG_ P2D_CMD2_DCDCOutputVltg_Set_57 : 39|12@1+ (0.1,-200) [-200|209.5] "V"  DCDC
 SG_ P2D_CMD2_Reserved3_57 : 51|4@1+ (1,0) [0|15] ""  DCDC
 SG_ P2D_CMD2_CommunicationState_57 : 55|2@1+ (1,0) [0|3] ""  DCDC
 SG_ P2D_CMD2_DCDC_Fault_Clear_57 : 57|1@1+ (1,0) [0|1] ""  DCDC
 SG_ P2D_CMD2_PCSOperationState_57 : 58|2@1+ (1,0) [0|3] ""  DCDC
 SG_ P2D_CMD2_DCDCLVoffControl_57 : 60|1@1+ (1,0) [0|1] ""  DCDC
 SG_ P2D_CMD2_Reserved4_57 : 61|3@1+ (1,0) [0|7] ""  DCDC

BO_ 2149416826 P2D_CMD2__58: 8 PC
 SG_ P2D_CMD2_CRC_58 : 0|8@1+ (1,0) [0|255] ""  DCDC
 SG_ P2D_CMD2_DCDCSerialNum_58 : 8|4@1+ (1,0) [0|15] ""  DCDC
 SG_ P2D_CMD2_DCDCEnable_58 : 12|1@1+ (1,0) [0|1] ""  DCDC
 SG_ P2D_CMD2_Reserved1_58 : 13|3@1+ (1,0) [0|7] ""  DCDC
 SG_ P2D_CMD2_DCDCWrkMdSwtch_58 : 16|2@1+ (1,0) [0|3] ""  DCDC
 SG_ P2D_CMD2_DCDCWrkMdSet_58 : 18|2@1+ (1,0) [0|3] ""  DCDC
 SG_ P2D_CMD2_Reserved2_58 : 20|3@1+ (1,0) [0|7] ""  DCDC
 SG_ P2D_CMD2_DCDCOutputCrrntSet_58 : 23|16@1+ (0.05,-2000) [-2000|1276.75] "A"  DCDC
 SG_ P2D_CMD2_DCDCOutputVltg_Set_58 : 39|12@1+ (0.1,-200) [-200|209.5] "V"  DCDC
 SG_ P2D_CMD2_Reserved3_58 : 51|4@1+ (1,0) [0|15] ""  DCDC
 SG_ P2D_CMD2_CommunicationState_58 : 55|2@1+ (1,0) [0|3] ""  DCDC
 SG_ P2D_CMD2_DCDC_Fault_Clear_58 : 57|1@1+ (1,0) [0|1] ""  DCDC
 SG_ P2D_CMD2_PCSOperationState_58 : 58|2@1+ (1,0) [0|3] ""  DCDC
 SG_ P2D_CMD2_DCDCLVoffControl_58 : 60|1@1+ (1,0) [0|1] ""  DCDC
 SG_ P2D_CMD2_Reserved4_58 : 61|3@1+ (1,0) [0|7] ""  DCDC

BO_ 2149416827 P2D_CMD2__59: 8 PC
 SG_ P2D_CMD2_CRC_59 : 0|8@1+ (1,0) [0|255] ""  DCDC
 SG_ P2D_CMD2_DCDCSerialNum_59 : 8|4@1+ (1,0) [0|15] ""  DCDC
 SG_ P2D_CMD2_DCDCEnable_59 : 12|1@1+ (1,0) [0|1] ""  DCDC
 SG_ P2D_CMD2_Reserved1_59 : 13|3@1+ (1,0) [0|7] ""  DCDC
 SG_ P2D_CMD2_DCDCWrkMdSwtch_59 : 16|2@1+ (1,0) [0|3] ""  DCDC
 SG_ P2D_CMD2_DCDCWrkMdSet_59 : 18|2@1+ (1,0) [0|3] ""  DCDC
 SG_ P2D_CMD2_Reserved2_59 : 20|3@1+ (1,0) [0|7] ""  DCDC
 SG_ P2D_CMD2_DCDCOutputCrrntSet_59 : 23|16@1+ (0.05,-2000) [-2000|1276.75] "A"  DCDC
 SG_ P2D_CMD2_DCDCOutputVltg_Set_59 : 39|12@1+ (0.1,-200) [-200|209.5] "V"  DCDC
 SG_ P2D_CMD2_Reserved3_59 : 51|4@1+ (1,0) [0|15] ""  DCDC
 SG_ P2D_CMD2_CommunicationState_59 : 55|2@1+ (1,0) [0|3] ""  DCDC
 SG_ P2D_CMD2_DCDC_Fault_Clear_59 : 57|1@1+ (1,0) [0|1] ""  DCDC
 SG_ P2D_CMD2_PCSOperationState_59 : 58|2@1+ (1,0) [0|3] ""  DCDC
 SG_ P2D_CMD2_DCDCLVoffControl_59 : 60|1@1+ (1,0) [0|1] ""  DCDC
 SG_ P2D_CMD2_Reserved4_59 : 61|3@1+ (1,0) [0|7] ""  DCDC

BO_ 2149416828 P2D_CMD2__60: 8 PC
 SG_ P2D_CMD2_CRC_60 : 0|8@1+ (1,0) [0|255] ""  DCDC
 SG_ P2D_CMD2_DCDCSerialNum_60 : 8|4@1+ (1,0) [0|15] ""  DCDC
 SG_ P2D_CMD2_DCDCEnable_60 : 12|1@1+ (1,0) [0|1] ""  DCDC
 SG_ P2D_CMD2_Reserved1_60 : 13|3@1+ (1,0) [0|7] ""  DCDC
 SG_ P2D_CMD2_DCDCWrkMdSwtch_60 : 16|2@1+ (1,0) [0|3] ""  DCDC
 SG_ P2D_CMD2_DCDCWrkMdSet_60 : 18|2@1+ (1,0) [0|3] ""  DCDC
 SG_ P2D_CMD2_Reserved2_60 : 20|3@1+ (1,0) [0|7] ""  DCDC
 SG_ P2D_CMD2_DCDCOutputCrrntSet_60 : 23|16@1+ (0.05,-2000) [-2000|1276.75] "A"  DCDC
 SG_ P2D_CMD2_DCDCOutputVltg_Set_60 : 39|12@1+ (0.1,-200) [-200|209.5] "V"  DCDC
 SG_ P2D_CMD2_Reserved3_60 : 51|4@1+ (1,0) [0|15] ""  DCDC
 SG_ P2D_CMD2_CommunicationState_60 : 55|2@1+ (1,0) [0|3] ""  DCDC
 SG_ P2D_CMD2_DCDC_Fault_Clear_60 : 57|1@1+ (1,0) [0|1] ""  DCDC
 SG_ P2D_CMD2_PCSOperationState_60 : 58|2@1+ (1,0) [0|3] ""  DCDC
 SG_ P2D_CMD2_DCDCLVoffControl_60 : 60|1@1+ (1,0) [0|1] ""  DCDC
 SG_ P2D_CMD2_Reserved4_60 : 61|3@1+ (1,0) [0|7] ""  DCDC

BO_ 2149416829 P2D_CMD2__61: 8 PC
 SG_ P2D_CMD2_CRC_61 : 0|8@1+ (1,0) [0|255] ""  DCDC
 SG_ P2D_CMD2_DCDCSerialNum_61 : 8|4@1+ (1,0) [0|15] ""  DCDC
 SG_ P2D_CMD2_DCDCEnable_61 : 12|1@1+ (1,0) [0|1] ""  DCDC
 SG_ P2D_CMD2_Reserved1_61 : 13|3@1+ (1,0) [0|7] ""  DCDC
 SG_ P2D_CMD2_DCDCWrkMdSwtch_61 : 16|2@1+ (1,0) [0|3] ""  DCDC
 SG_ P2D_CMD2_DCDCWrkMdSet_61 : 18|2@1+ (1,0) [0|3] ""  DCDC
 SG_ P2D_CMD2_Reserved2_61 : 20|3@1+ (1,0) [0|7] ""  DCDC
 SG_ P2D_CMD2_DCDCOutputCrrntSet_61 : 23|16@1+ (0.05,-2000) [-2000|1276.75] "A"  DCDC
 SG_ P2D_CMD2_DCDCOutputVltg_Set_61 : 39|12@1+ (0.1,-200) [-200|209.5] "V"  DCDC
 SG_ P2D_CMD2_Reserved3_61 : 51|4@1+ (1,0) [0|15] ""  DCDC
 SG_ P2D_CMD2_CommunicationState_61 : 55|2@1+ (1,0) [0|3] ""  DCDC
 SG_ P2D_CMD2_DCDC_Fault_Clear_61 : 57|1@1+ (1,0) [0|1] ""  DCDC
 SG_ P2D_CMD2_PCSOperationState_61 : 58|2@1+ (1,0) [0|3] ""  DCDC
 SG_ P2D_CMD2_DCDCLVoffControl_61 : 60|1@1+ (1,0) [0|1] ""  DCDC
 SG_ P2D_CMD2_Reserved4_61 : 61|3@1+ (1,0) [0|7] ""  DCDC

BO_ 2149416830 P2D_CMD2__62: 8 PC
 SG_ P2D_CMD2_CRC_62 : 0|8@1+ (1,0) [0|255] ""  DCDC
 SG_ P2D_CMD2_DCDCSerialNum_62 : 8|4@1+ (1,0) [0|15] ""  DCDC
 SG_ P2D_CMD2_DCDCEnable_62 : 12|1@1+ (1,0) [0|1] ""  DCDC
 SG_ P2D_CMD2_Reserved1_62 : 13|3@1+ (1,0) [0|7] ""  DCDC
 SG_ P2D_CMD2_DCDCWrkMdSwtch_62 : 16|2@1+ (1,0) [0|3] ""  DCDC
 SG_ P2D_CMD2_DCDCWrkMdSet_62 : 18|2@1+ (1,0) [0|3] ""  DCDC
 SG_ P2D_CMD2_Reserved2_62 : 20|3@1+ (1,0) [0|7] ""  DCDC
 SG_ P2D_CMD2_DCDCOutputCrrntSet_62 : 23|16@1+ (0.05,-2000) [-2000|1276.75] "A"  DCDC
 SG_ P2D_CMD2_DCDCOutputVltg_Set_62 : 39|12@1+ (0.1,-200) [-200|209.5] "V"  DCDC
 SG_ P2D_CMD2_Reserved3_62 : 51|4@1+ (1,0) [0|15] ""  DCDC
 SG_ P2D_CMD2_CommunicationState_62 : 55|2@1+ (1,0) [0|3] ""  DCDC
 SG_ P2D_CMD2_DCDC_Fault_Clear_62 : 57|1@1+ (1,0) [0|1] ""  DCDC
 SG_ P2D_CMD2_PCSOperationState_62 : 58|2@1+ (1,0) [0|3] ""  DCDC
 SG_ P2D_CMD2_DCDCLVoffControl_62 : 60|1@1+ (1,0) [0|1] ""  DCDC
 SG_ P2D_CMD2_Reserved4_62 : 61|3@1+ (1,0) [0|7] ""  DCDC

BO_ 2149416831 P2D_CMD2__63: 8 PC
 SG_ P2D_CMD2_CRC_63 : 0|8@1+ (1,0) [0|255] ""  DCDC
 SG_ P2D_CMD2_DCDCSerialNum_63 : 8|4@1+ (1,0) [0|15] ""  DCDC
 SG_ P2D_CMD2_DCDCEnable_63 : 12|1@1+ (1,0) [0|1] ""  DCDC
 SG_ P2D_CMD2_Reserved1_63 : 13|3@1+ (1,0) [0|7] ""  DCDC
 SG_ P2D_CMD2_DCDCWrkMdSwtch_63 : 16|2@1+ (1,0) [0|3] ""  DCDC
 SG_ P2D_CMD2_DCDCWrkMdSet_63 : 18|2@1+ (1,0) [0|3] ""  DCDC
 SG_ P2D_CMD2_Reserved2_63 : 20|3@1+ (1,0) [0|7] ""  DCDC
 SG_ P2D_CMD2_DCDCOutputCrrntSet_63 : 23|16@1+ (0.05,-2000) [-2000|1276.75] "A"  DCDC
 SG_ P2D_CMD2_DCDCOutputVltg_Set_63 : 39|12@1+ (0.1,-200) [-200|209.5] "V"  DCDC
 SG_ P2D_CMD2_Reserved3_63 : 51|4@1+ (1,0) [0|15] ""  DCDC
 SG_ P2D_CMD2_CommunicationState_63 : 55|2@1+ (1,0) [0|3] ""  DCDC
 SG_ P2D_CMD2_DCDC_Fault_Clear_63 : 57|1@1+ (1,0) [0|1] ""  DCDC
 SG_ P2D_CMD2_PCSOperationState_63 : 58|2@1+ (1,0) [0|3] ""  DCDC
 SG_ P2D_CMD2_DCDCLVoffControl_63 : 60|1@1+ (1,0) [0|1] ""  DCDC
 SG_ P2D_CMD2_Reserved4_63 : 61|3@1+ (1,0) [0|7] ""  DCDC

BO_ 2149482478 P2D_Cfg5: 8 PC
 SG_ P2D_Cfg5_DCDC_Add : 0|8@1+ (1,0) [0|255] ""  DCDC
 SG_ P2D_Cfg5_Data0 : 8|8@1+ (1,0) [0|255] ""  DCDC
 SG_ P2D_Cfg5_Data1 : 16|8@1+ (1,0) [0|255] ""  DCDC
 SG_ P2D_Cfg5_Data2 : 24|8@1+ (1,0) [0|255] ""  DCDC
 SG_ P2D_Cfg5_Data3 : 32|8@1+ (1,0) [0|255] ""  DCDC
 SG_ P2D_Cfg5_Data4 : 40|8@1+ (1,0) [0|255] ""  DCDC
 SG_ P2D_Cfg5_Data5 : 48|8@1+ (1,0) [0|255] ""  DCDC
 SG_ P2D_Cfg5_Data6 : 56|8@1+ (1,0) [0|255] ""  DCDC

BO_ 2149547841 D2P_ALARM__01: 8 DCDC
 SG_ D2P_ALARM_EnvExtreOverTemp : 0|1@1+ (1,0) [0|1] ""  PC
 SG_ D2P_ALARM_EnvOverTemp : 1|1@1+ (1,0) [0|1] ""  PC
 SG_ D2P_ALARM_MosOverTemp : 2|1@1+ (1,0) [0|1] ""  PC
 SG_ D2P_ALARM_MosExtreOverTemp : 3|1@1+ (1,0) [0|1] ""  PC
 SG_ D2P_ALARM_HighSideOverVolt : 4|1@1+ (1,0) [0|1] ""  PC
 SG_ D2P_ALARM_HighSideUnderVolt : 5|1@1+ (1,0) [0|1] ""  PC
 SG_ D2P_ALARM_LowSideOverVolt : 6|1@1+ (1,0) [0|1] ""  PC
 SG_ D2P_ALARM_HighSideOverCurr : 7|1@1+ (1,0) [0|1] ""  PC
 SG_ D2P_ALARM_LowSideOverCurr_HW : 8|1@1+ (1,0) [0|1] ""  PC
 SG_ D2P_ALARM_LowSideOverCurr_SW : 9|1@1+ (1,0) [0|1] ""  PC
 SG_ D2P_ALARM_SecSideOverCurr_HW : 10|1@1+ (1,0) [0|1] ""  PC
 SG_ D2P_ALARM_SecSideOverCurr_SW : 11|1@1+ (1,0) [0|1] ""  PC
 SG_ D2P_ALARM_PriSideOverCurr_HW : 12|1@1+ (1,0) [0|1] ""  PC
 SG_ D2P_ALARM_PriSideOverCurr_SW : 13|1@1+ (1,0) [0|1] ""  PC
 SG_ D2P_ALARM_LowPowerSupplyErr : 14|1@1+ (1,0) [0|1] ""  PC
 SG_ D2P_ALARM_MBMUComErr : 15|1@1+ (1,0) [0|1] ""  PC
 SG_ D2P_ALARM_DCDCMsTeSaplgErr : 16|1@1+ (1,0) [0|1] ""  PC
 SG_ D2P_ALARM_DCDCTeSaplgErr : 17|1@1+ (1,0) [0|1] ""  PC
 SG_ D2P_ALARM_VoltSamplingErr : 18|1@1+ (1,0) [0|1] ""  PC
 SG_ D2P_ALARM_HgSdCuSaplgErr : 19|1@1+ (1,0) [0|1] ""  PC
 SG_ D2P_ALARM_CtrlCurrSamplingErr : 20|1@1+ (1,0) [0|1] ""  PC
 SG_ D2P_ALARM_BypassFail : 21|1@1+ (1,0) [0|1] ""  PC
 SG_ D2P_ALARM_Reserve1 : 22|1@1+ (1,0) [0|1] ""  PC
 SG_ D2P_ALARM_Reserve2 : 23|1@1+ (1,0) [0|1] ""  PC
 SG_ D2P_ALARM_Reserve3 : 24|1@1+ (1,0) [0|1] ""  PC
 SG_ D2P_ALARM_Reserve4 : 25|1@1+ (1,0) [0|1] ""  PC
 SG_ D2P_ALARM_Reserve5 : 26|1@1+ (1,0) [0|1] ""  PC
 SG_ D2P_ALARM_Reserve6 : 27|1@1+ (1,0) [0|1] ""  PC
 SG_ D2P_ALARM_Reserve7 : 28|1@1+ (1,0) [0|1] ""  PC
 SG_ D2P_ALARM_Reserve8 : 29|1@1+ (1,0) [0|1] ""  PC
 SG_ D2P_ALARM_Reserve9 : 30|1@1+ (1,0) [0|1] ""  PC
 SG_ D2P_ALARM_Reserve10 : 31|1@1+ (1,0) [0|1] ""  PC
 SG_ D2P_ALARM_Reserve11 : 32|32@1+ (1,0) [0|4294967295] ""  PC

BO_ 2149547842 D2P_ALARM__02: 8 DCDC
 SG_ D2P_ALARM_EnvExtreOverTemp : 0|1@1+ (1,0) [0|1] ""  PC
 SG_ D2P_ALARM_EnvOverTemp : 1|1@1+ (1,0) [0|1] ""  PC
 SG_ D2P_ALARM_MosOverTemp : 2|1@1+ (1,0) [0|1] ""  PC
 SG_ D2P_ALARM_MosExtreOverTemp : 3|1@1+ (1,0) [0|1] ""  PC
 SG_ D2P_ALARM_HighSideOverVolt : 4|1@1+ (1,0) [0|1] ""  PC
 SG_ D2P_ALARM_HighSideUnderVolt : 5|1@1+ (1,0) [0|1] ""  PC
 SG_ D2P_ALARM_LowSideOverVolt : 6|1@1+ (1,0) [0|1] ""  PC
 SG_ D2P_ALARM_HighSideOverCurr : 7|1@1+ (1,0) [0|1] ""  PC
 SG_ D2P_ALARM_LowSideOverCurr_HW : 8|1@1+ (1,0) [0|1] ""  PC
 SG_ D2P_ALARM_LowSideOverCurr_SW : 9|1@1+ (1,0) [0|1] ""  PC
 SG_ D2P_ALARM_SecSideOverCurr_HW : 10|1@1+ (1,0) [0|1] ""  PC
 SG_ D2P_ALARM_SecSideOverCurr_SW : 11|1@1+ (1,0) [0|1] ""  PC
 SG_ D2P_ALARM_PriSideOverCurr_HW : 12|1@1+ (1,0) [0|1] ""  PC
 SG_ D2P_ALARM_PriSideOverCurr_SW : 13|1@1+ (1,0) [0|1] ""  PC
 SG_ D2P_ALARM_LowPowerSupplyErr : 14|1@1+ (1,0) [0|1] ""  PC
 SG_ D2P_ALARM_MBMUComErr : 15|1@1+ (1,0) [0|1] ""  PC
 SG_ D2P_ALARM_DCDCMsTeSaplgErr : 16|1@1+ (1,0) [0|1] ""  PC
 SG_ D2P_ALARM_DCDCTeSaplgErr : 17|1@1+ (1,0) [0|1] ""  PC
 SG_ D2P_ALARM_VoltSamplingErr : 18|1@1+ (1,0) [0|1] ""  PC
 SG_ D2P_ALARM_HgSdCuSaplgErr : 19|1@1+ (1,0) [0|1] ""  PC
 SG_ D2P_ALARM_CtrlCurrSamplingErr : 20|1@1+ (1,0) [0|1] ""  PC
 SG_ D2P_ALARM_BypassFail : 21|1@1+ (1,0) [0|1] ""  PC
 SG_ D2P_ALARM_Reserve1 : 22|1@1+ (1,0) [0|1] ""  PC
 SG_ D2P_ALARM_Reserve2 : 23|1@1+ (1,0) [0|1] ""  PC
 SG_ D2P_ALARM_Reserve3 : 24|1@1+ (1,0) [0|1] ""  PC
 SG_ D2P_ALARM_Reserve4 : 25|1@1+ (1,0) [0|1] ""  PC
 SG_ D2P_ALARM_Reserve5 : 26|1@1+ (1,0) [0|1] ""  PC
 SG_ D2P_ALARM_Reserve6 : 27|1@1+ (1,0) [0|1] ""  PC
 SG_ D2P_ALARM_Reserve7 : 28|1@1+ (1,0) [0|1] ""  PC
 SG_ D2P_ALARM_Reserve8 : 29|1@1+ (1,0) [0|1] ""  PC
 SG_ D2P_ALARM_Reserve9 : 30|1@1+ (1,0) [0|1] ""  PC
 SG_ D2P_ALARM_Reserve10 : 31|1@1+ (1,0) [0|1] ""  PC
 SG_ D2P_ALARM_Reserve11 : 32|32@1+ (1,0) [0|4294967295] ""  PC

BO_ 2149547843 D2P_ALARM__03: 8 DCDC
 SG_ D2P_ALARM_EnvExtreOverTemp : 0|1@1+ (1,0) [0|1] ""  PC
 SG_ D2P_ALARM_EnvOverTemp : 1|1@1+ (1,0) [0|1] ""  PC
 SG_ D2P_ALARM_MosOverTemp : 2|1@1+ (1,0) [0|1] ""  PC
 SG_ D2P_ALARM_MosExtreOverTemp : 3|1@1+ (1,0) [0|1] ""  PC
 SG_ D2P_ALARM_HighSideOverVolt : 4|1@1+ (1,0) [0|1] ""  PC
 SG_ D2P_ALARM_HighSideUnderVolt : 5|1@1+ (1,0) [0|1] ""  PC
 SG_ D2P_ALARM_LowSideOverVolt : 6|1@1+ (1,0) [0|1] ""  PC
 SG_ D2P_ALARM_HighSideOverCurr : 7|1@1+ (1,0) [0|1] ""  PC
 SG_ D2P_ALARM_LowSideOverCurr_HW : 8|1@1+ (1,0) [0|1] ""  PC
 SG_ D2P_ALARM_LowSideOverCurr_SW : 9|1@1+ (1,0) [0|1] ""  PC
 SG_ D2P_ALARM_SecSideOverCurr_HW : 10|1@1+ (1,0) [0|1] ""  PC
 SG_ D2P_ALARM_SecSideOverCurr_SW : 11|1@1+ (1,0) [0|1] ""  PC
 SG_ D2P_ALARM_PriSideOverCurr_HW : 12|1@1+ (1,0) [0|1] ""  PC
 SG_ D2P_ALARM_PriSideOverCurr_SW : 13|1@1+ (1,0) [0|1] ""  PC
 SG_ D2P_ALARM_LowPowerSupplyErr : 14|1@1+ (1,0) [0|1] ""  PC
 SG_ D2P_ALARM_MBMUComErr : 15|1@1+ (1,0) [0|1] ""  PC
 SG_ D2P_ALARM_DCDCMsTeSaplgErr : 16|1@1+ (1,0) [0|1] ""  PC
 SG_ D2P_ALARM_DCDCTeSaplgErr : 17|1@1+ (1,0) [0|1] ""  PC
 SG_ D2P_ALARM_VoltSamplingErr : 18|1@1+ (1,0) [0|1] ""  PC
 SG_ D2P_ALARM_HgSdCuSaplgErr : 19|1@1+ (1,0) [0|1] ""  PC
 SG_ D2P_ALARM_CtrlCurrSamplingErr : 20|1@1+ (1,0) [0|1] ""  PC
 SG_ D2P_ALARM_BypassFail : 21|1@1+ (1,0) [0|1] ""  PC
 SG_ D2P_ALARM_Reserve1 : 22|1@1+ (1,0) [0|1] ""  PC
 SG_ D2P_ALARM_Reserve2 : 23|1@1+ (1,0) [0|1] ""  PC
 SG_ D2P_ALARM_Reserve3 : 24|1@1+ (1,0) [0|1] ""  PC
 SG_ D2P_ALARM_Reserve4 : 25|1@1+ (1,0) [0|1] ""  PC
 SG_ D2P_ALARM_Reserve5 : 26|1@1+ (1,0) [0|1] ""  PC
 SG_ D2P_ALARM_Reserve6 : 27|1@1+ (1,0) [0|1] ""  PC
 SG_ D2P_ALARM_Reserve7 : 28|1@1+ (1,0) [0|1] ""  PC
 SG_ D2P_ALARM_Reserve8 : 29|1@1+ (1,0) [0|1] ""  PC
 SG_ D2P_ALARM_Reserve9 : 30|1@1+ (1,0) [0|1] ""  PC
 SG_ D2P_ALARM_Reserve10 : 31|1@1+ (1,0) [0|1] ""  PC
 SG_ D2P_ALARM_Reserve11 : 32|32@1+ (1,0) [0|4294967295] ""  PC

BO_ 2149547844 D2P_ALARM__04: 8 DCDC
 SG_ D2P_ALARM_EnvExtreOverTemp : 0|1@1+ (1,0) [0|1] ""  PC
 SG_ D2P_ALARM_EnvOverTemp : 1|1@1+ (1,0) [0|1] ""  PC
 SG_ D2P_ALARM_MosOverTemp : 2|1@1+ (1,0) [0|1] ""  PC
 SG_ D2P_ALARM_MosExtreOverTemp : 3|1@1+ (1,0) [0|1] ""  PC
 SG_ D2P_ALARM_HighSideOverVolt : 4|1@1+ (1,0) [0|1] ""  PC
 SG_ D2P_ALARM_HighSideUnderVolt : 5|1@1+ (1,0) [0|1] ""  PC
 SG_ D2P_ALARM_LowSideOverVolt : 6|1@1+ (1,0) [0|1] ""  PC
 SG_ D2P_ALARM_HighSideOverCurr : 7|1@1+ (1,0) [0|1] ""  PC
 SG_ D2P_ALARM_LowSideOverCurr_HW : 8|1@1+ (1,0) [0|1] ""  PC
 SG_ D2P_ALARM_LowSideOverCurr_SW : 9|1@1+ (1,0) [0|1] ""  PC
 SG_ D2P_ALARM_SecSideOverCurr_HW : 10|1@1+ (1,0) [0|1] ""  PC
 SG_ D2P_ALARM_SecSideOverCurr_SW : 11|1@1+ (1,0) [0|1] ""  PC
 SG_ D2P_ALARM_PriSideOverCurr_HW : 12|1@1+ (1,0) [0|1] ""  PC
 SG_ D2P_ALARM_PriSideOverCurr_SW : 13|1@1+ (1,0) [0|1] ""  PC
 SG_ D2P_ALARM_LowPowerSupplyErr : 14|1@1+ (1,0) [0|1] ""  PC
 SG_ D2P_ALARM_MBMUComErr : 15|1@1+ (1,0) [0|1] ""  PC
 SG_ D2P_ALARM_DCDCMsTeSaplgErr : 16|1@1+ (1,0) [0|1] ""  PC
 SG_ D2P_ALARM_DCDCTeSaplgErr : 17|1@1+ (1,0) [0|1] ""  PC
 SG_ D2P_ALARM_VoltSamplingErr : 18|1@1+ (1,0) [0|1] ""  PC
 SG_ D2P_ALARM_HgSdCuSaplgErr : 19|1@1+ (1,0) [0|1] ""  PC
 SG_ D2P_ALARM_CtrlCurrSamplingErr : 20|1@1+ (1,0) [0|1] ""  PC
 SG_ D2P_ALARM_BypassFail : 21|1@1+ (1,0) [0|1] ""  PC
 SG_ D2P_ALARM_Reserve1 : 22|1@1+ (1,0) [0|1] ""  PC
 SG_ D2P_ALARM_Reserve2 : 23|1@1+ (1,0) [0|1] ""  PC
 SG_ D2P_ALARM_Reserve3 : 24|1@1+ (1,0) [0|1] ""  PC
 SG_ D2P_ALARM_Reserve4 : 25|1@1+ (1,0) [0|1] ""  PC
 SG_ D2P_ALARM_Reserve5 : 26|1@1+ (1,0) [0|1] ""  PC
 SG_ D2P_ALARM_Reserve6 : 27|1@1+ (1,0) [0|1] ""  PC
 SG_ D2P_ALARM_Reserve7 : 28|1@1+ (1,0) [0|1] ""  PC
 SG_ D2P_ALARM_Reserve8 : 29|1@1+ (1,0) [0|1] ""  PC
 SG_ D2P_ALARM_Reserve9 : 30|1@1+ (1,0) [0|1] ""  PC
 SG_ D2P_ALARM_Reserve10 : 31|1@1+ (1,0) [0|1] ""  PC
 SG_ D2P_ALARM_Reserve11 : 32|32@1+ (1,0) [0|4294967295] ""  PC

BO_ 2149547845 D2P_ALARM__05: 8 DCDC
 SG_ D2P_ALARM_EnvExtreOverTemp : 0|1@1+ (1,0) [0|1] ""  PC
 SG_ D2P_ALARM_EnvOverTemp : 1|1@1+ (1,0) [0|1] ""  PC
 SG_ D2P_ALARM_MosOverTemp : 2|1@1+ (1,0) [0|1] ""  PC
 SG_ D2P_ALARM_MosExtreOverTemp : 3|1@1+ (1,0) [0|1] ""  PC
 SG_ D2P_ALARM_HighSideOverVolt : 4|1@1+ (1,0) [0|1] ""  PC
 SG_ D2P_ALARM_HighSideUnderVolt : 5|1@1+ (1,0) [0|1] ""  PC
 SG_ D2P_ALARM_LowSideOverVolt : 6|1@1+ (1,0) [0|1] ""  PC
 SG_ D2P_ALARM_HighSideOverCurr : 7|1@1+ (1,0) [0|1] ""  PC
 SG_ D2P_ALARM_LowSideOverCurr_HW : 8|1@1+ (1,0) [0|1] ""  PC
 SG_ D2P_ALARM_LowSideOverCurr_SW : 9|1@1+ (1,0) [0|1] ""  PC
 SG_ D2P_ALARM_SecSideOverCurr_HW : 10|1@1+ (1,0) [0|1] ""  PC
 SG_ D2P_ALARM_SecSideOverCurr_SW : 11|1@1+ (1,0) [0|1] ""  PC
 SG_ D2P_ALARM_PriSideOverCurr_HW : 12|1@1+ (1,0) [0|1] ""  PC
 SG_ D2P_ALARM_PriSideOverCurr_SW : 13|1@1+ (1,0) [0|1] ""  PC
 SG_ D2P_ALARM_LowPowerSupplyErr : 14|1@1+ (1,0) [0|1] ""  PC
 SG_ D2P_ALARM_MBMUComErr : 15|1@1+ (1,0) [0|1] ""  PC
 SG_ D2P_ALARM_DCDCMsTeSaplgErr : 16|1@1+ (1,0) [0|1] ""  PC
 SG_ D2P_ALARM_DCDCTeSaplgErr : 17|1@1+ (1,0) [0|1] ""  PC
 SG_ D2P_ALARM_VoltSamplingErr : 18|1@1+ (1,0) [0|1] ""  PC
 SG_ D2P_ALARM_HgSdCuSaplgErr : 19|1@1+ (1,0) [0|1] ""  PC
 SG_ D2P_ALARM_CtrlCurrSamplingErr : 20|1@1+ (1,0) [0|1] ""  PC
 SG_ D2P_ALARM_BypassFail : 21|1@1+ (1,0) [0|1] ""  PC
 SG_ D2P_ALARM_Reserve1 : 22|1@1+ (1,0) [0|1] ""  PC
 SG_ D2P_ALARM_Reserve2 : 23|1@1+ (1,0) [0|1] ""  PC
 SG_ D2P_ALARM_Reserve3 : 24|1@1+ (1,0) [0|1] ""  PC
 SG_ D2P_ALARM_Reserve4 : 25|1@1+ (1,0) [0|1] ""  PC
 SG_ D2P_ALARM_Reserve5 : 26|1@1+ (1,0) [0|1] ""  PC
 SG_ D2P_ALARM_Reserve6 : 27|1@1+ (1,0) [0|1] ""  PC
 SG_ D2P_ALARM_Reserve7 : 28|1@1+ (1,0) [0|1] ""  PC
 SG_ D2P_ALARM_Reserve8 : 29|1@1+ (1,0) [0|1] ""  PC
 SG_ D2P_ALARM_Reserve9 : 30|1@1+ (1,0) [0|1] ""  PC
 SG_ D2P_ALARM_Reserve10 : 31|1@1+ (1,0) [0|1] ""  PC
 SG_ D2P_ALARM_Reserve11 : 32|32@1+ (1,0) [0|4294967295] ""  PC

BO_ 2149547846 D2P_ALARM__06: 8 DCDC
 SG_ D2P_ALARM_EnvExtreOverTemp : 0|1@1+ (1,0) [0|1] ""  PC
 SG_ D2P_ALARM_EnvOverTemp : 1|1@1+ (1,0) [0|1] ""  PC
 SG_ D2P_ALARM_MosOverTemp : 2|1@1+ (1,0) [0|1] ""  PC
 SG_ D2P_ALARM_MosExtreOverTemp : 3|1@1+ (1,0) [0|1] ""  PC
 SG_ D2P_ALARM_HighSideOverVolt : 4|1@1+ (1,0) [0|1] ""  PC
 SG_ D2P_ALARM_HighSideUnderVolt : 5|1@1+ (1,0) [0|1] ""  PC
 SG_ D2P_ALARM_LowSideOverVolt : 6|1@1+ (1,0) [0|1] ""  PC
 SG_ D2P_ALARM_HighSideOverCurr : 7|1@1+ (1,0) [0|1] ""  PC
 SG_ D2P_ALARM_LowSideOverCurr_HW : 8|1@1+ (1,0) [0|1] ""  PC
 SG_ D2P_ALARM_LowSideOverCurr_SW : 9|1@1+ (1,0) [0|1] ""  PC
 SG_ D2P_ALARM_SecSideOverCurr_HW : 10|1@1+ (1,0) [0|1] ""  PC
 SG_ D2P_ALARM_SecSideOverCurr_SW : 11|1@1+ (1,0) [0|1] ""  PC
 SG_ D2P_ALARM_PriSideOverCurr_HW : 12|1@1+ (1,0) [0|1] ""  PC
 SG_ D2P_ALARM_PriSideOverCurr_SW : 13|1@1+ (1,0) [0|1] ""  PC
 SG_ D2P_ALARM_LowPowerSupplyErr : 14|1@1+ (1,0) [0|1] ""  PC
 SG_ D2P_ALARM_MBMUComErr : 15|1@1+ (1,0) [0|1] ""  PC
 SG_ D2P_ALARM_DCDCMsTeSaplgErr : 16|1@1+ (1,0) [0|1] ""  PC
 SG_ D2P_ALARM_DCDCTeSaplgErr : 17|1@1+ (1,0) [0|1] ""  PC
 SG_ D2P_ALARM_VoltSamplingErr : 18|1@1+ (1,0) [0|1] ""  PC
 SG_ D2P_ALARM_HgSdCuSaplgErr : 19|1@1+ (1,0) [0|1] ""  PC
 SG_ D2P_ALARM_CtrlCurrSamplingErr : 20|1@1+ (1,0) [0|1] ""  PC
 SG_ D2P_ALARM_BypassFail : 21|1@1+ (1,0) [0|1] ""  PC
 SG_ D2P_ALARM_Reserve1 : 22|1@1+ (1,0) [0|1] ""  PC
 SG_ D2P_ALARM_Reserve2 : 23|1@1+ (1,0) [0|1] ""  PC
 SG_ D2P_ALARM_Reserve3 : 24|1@1+ (1,0) [0|1] ""  PC
 SG_ D2P_ALARM_Reserve4 : 25|1@1+ (1,0) [0|1] ""  PC
 SG_ D2P_ALARM_Reserve5 : 26|1@1+ (1,0) [0|1] ""  PC
 SG_ D2P_ALARM_Reserve6 : 27|1@1+ (1,0) [0|1] ""  PC
 SG_ D2P_ALARM_Reserve7 : 28|1@1+ (1,0) [0|1] ""  PC
 SG_ D2P_ALARM_Reserve8 : 29|1@1+ (1,0) [0|1] ""  PC
 SG_ D2P_ALARM_Reserve9 : 30|1@1+ (1,0) [0|1] ""  PC
 SG_ D2P_ALARM_Reserve10 : 31|1@1+ (1,0) [0|1] ""  PC
 SG_ D2P_ALARM_Reserve11 : 32|32@1+ (1,0) [0|4294967295] ""  PC

BO_ 2149547847 D2P_ALARM__07: 8 DCDC
 SG_ D2P_ALARM_EnvExtreOverTemp : 0|1@1+ (1,0) [0|1] ""  PC
 SG_ D2P_ALARM_EnvOverTemp : 1|1@1+ (1,0) [0|1] ""  PC
 SG_ D2P_ALARM_MosOverTemp : 2|1@1+ (1,0) [0|1] ""  PC
 SG_ D2P_ALARM_MosExtreOverTemp : 3|1@1+ (1,0) [0|1] ""  PC
 SG_ D2P_ALARM_HighSideOverVolt : 4|1@1+ (1,0) [0|1] ""  PC
 SG_ D2P_ALARM_HighSideUnderVolt : 5|1@1+ (1,0) [0|1] ""  PC
 SG_ D2P_ALARM_LowSideOverVolt : 6|1@1+ (1,0) [0|1] ""  PC
 SG_ D2P_ALARM_HighSideOverCurr : 7|1@1+ (1,0) [0|1] ""  PC
 SG_ D2P_ALARM_LowSideOverCurr_HW : 8|1@1+ (1,0) [0|1] ""  PC
 SG_ D2P_ALARM_LowSideOverCurr_SW : 9|1@1+ (1,0) [0|1] ""  PC
 SG_ D2P_ALARM_SecSideOverCurr_HW : 10|1@1+ (1,0) [0|1] ""  PC
 SG_ D2P_ALARM_SecSideOverCurr_SW : 11|1@1+ (1,0) [0|1] ""  PC
 SG_ D2P_ALARM_PriSideOverCurr_HW : 12|1@1+ (1,0) [0|1] ""  PC
 SG_ D2P_ALARM_PriSideOverCurr_SW : 13|1@1+ (1,0) [0|1] ""  PC
 SG_ D2P_ALARM_LowPowerSupplyErr : 14|1@1+ (1,0) [0|1] ""  PC
 SG_ D2P_ALARM_MBMUComErr : 15|1@1+ (1,0) [0|1] ""  PC
 SG_ D2P_ALARM_DCDCMsTeSaplgErr : 16|1@1+ (1,0) [0|1] ""  PC
 SG_ D2P_ALARM_DCDCTeSaplgErr : 17|1@1+ (1,0) [0|1] ""  PC
 SG_ D2P_ALARM_VoltSamplingErr : 18|1@1+ (1,0) [0|1] ""  PC
 SG_ D2P_ALARM_HgSdCuSaplgErr : 19|1@1+ (1,0) [0|1] ""  PC
 SG_ D2P_ALARM_CtrlCurrSamplingErr : 20|1@1+ (1,0) [0|1] ""  PC
 SG_ D2P_ALARM_BypassFail : 21|1@1+ (1,0) [0|1] ""  PC
 SG_ D2P_ALARM_Reserve1 : 22|1@1+ (1,0) [0|1] ""  PC
 SG_ D2P_ALARM_Reserve2 : 23|1@1+ (1,0) [0|1] ""  PC
 SG_ D2P_ALARM_Reserve3 : 24|1@1+ (1,0) [0|1] ""  PC
 SG_ D2P_ALARM_Reserve4 : 25|1@1+ (1,0) [0|1] ""  PC
 SG_ D2P_ALARM_Reserve5 : 26|1@1+ (1,0) [0|1] ""  PC
 SG_ D2P_ALARM_Reserve6 : 27|1@1+ (1,0) [0|1] ""  PC
 SG_ D2P_ALARM_Reserve7 : 28|1@1+ (1,0) [0|1] ""  PC
 SG_ D2P_ALARM_Reserve8 : 29|1@1+ (1,0) [0|1] ""  PC
 SG_ D2P_ALARM_Reserve9 : 30|1@1+ (1,0) [0|1] ""  PC
 SG_ D2P_ALARM_Reserve10 : 31|1@1+ (1,0) [0|1] ""  PC
 SG_ D2P_ALARM_Reserve11 : 32|32@1+ (1,0) [0|4294967295] ""  PC

CM_ SG_ 2149416775 P2D_CMD2_CRC_07 "预留 （这里没必要做CRC校验吧？）";
CM_ SG_ 2149416775 P2D_CMD2_DCDCSerialNum_07 "预留（原为DCDC编号）";
CM_ SG_ 2149416775 P2D_CMD2_DCDCEnable_07 "使能DCDC命令";
CM_ SG_ 2149416775 P2D_CMD2_Reserved1_07 "预留1";
CM_ SG_ 2149416775 P2D_CMD2_DCDCWrkMdSwtch_07 "DCDC工作状态切换";
CM_ SG_ 2149416775 P2D_CMD2_DCDCWrkMdSet_07 "DCDC工作模式设定";
CM_ SG_ 2149416775 P2D_CMD2_Reserved2_07 "预留2";
CM_ SG_ 2149416775 P2D_CMD2_DCDCOutputCrrntSet_07 "电池电流设定（放正充负）
电池电流=DC低压端电流+DC高压端电流";
CM_ SG_ 2149416775 P2D_CMD2_DCDCOutputVltg_Set_07 "DCDC输出电压设定";
CM_ SG_ 2149416775 P2D_CMD2_Reserved3_07 "预留3";
CM_ SG_ 2149416775 P2D_CMD2_CommunicationState_07 "PC与DCDC通讯状态";
CM_ SG_ 2149416775 P2D_CMD2_DCDC_Fault_Clear_07 "DCDC故障清除指令";
CM_ SG_ 2149416775 P2D_CMD2_PCSOperationState_07 "PCS运行状态（预留）";
CM_ SG_ 2149416775 P2D_CMD2_DCDCLVoffControl_07 "DCDC低压下电控制";
CM_ SG_ 2149416775 P2D_CMD2_Reserved4_07 "预留4";
CM_ SG_ 2149416776 P2D_CMD2_CRC_08 "预留 （这里没必要做CRC校验吧？）";
CM_ SG_ 2149416776 P2D_CMD2_DCDCSerialNum_08 "预留（原为DCDC编号）";
CM_ SG_ 2149416776 P2D_CMD2_DCDCEnable_08 "使能DCDC命令";
CM_ SG_ 2149416776 P2D_CMD2_Reserved1_08 "预留1";
CM_ SG_ 2149416776 P2D_CMD2_DCDCWrkMdSwtch_08 "DCDC工作状态切换";
CM_ SG_ 2149416776 P2D_CMD2_DCDCWrkMdSet_08 "DCDC工作模式设定";
CM_ SG_ 2149416776 P2D_CMD2_Reserved2_08 "预留2";
CM_ SG_ 2149416776 P2D_CMD2_DCDCOutputCrrntSet_08 "电池电流设定（放正充负）
电池电流=DC低压端电流+DC高压端电流";
CM_ SG_ 2149416776 P2D_CMD2_DCDCOutputVltg_Set_08 "DCDC输出电压设定";
CM_ SG_ 2149416776 P2D_CMD2_Reserved3_08 "预留3";
CM_ SG_ 2149416776 P2D_CMD2_CommunicationState_08 "PC与DCDC通讯状态";
CM_ SG_ 2149416776 P2D_CMD2_DCDC_Fault_Clear_08 "DCDC故障清除指令";
CM_ SG_ 2149416776 P2D_CMD2_PCSOperationState_08 "PCS运行状态（预留）";
CM_ SG_ 2149416776 P2D_CMD2_DCDCLVoffControl_08 "DCDC低压下电控制";
CM_ SG_ 2149416776 P2D_CMD2_Reserved4_08 "预留4";
CM_ SG_ 2149416777 P2D_CMD2_CRC_09 "预留 （这里没必要做CRC校验吧？）";
CM_ SG_ 2149416777 P2D_CMD2_DCDCSerialNum_09 "预留（原为DCDC编号）";
CM_ SG_ 2149416777 P2D_CMD2_DCDCEnable_09 "使能DCDC命令";
CM_ SG_ 2149416777 P2D_CMD2_Reserved1_09 "预留1";
CM_ SG_ 2149416777 P2D_CMD2_DCDCWrkMdSwtch_09 "DCDC工作状态切换";
CM_ SG_ 2149416777 P2D_CMD2_DCDCWrkMdSet_09 "DCDC工作模式设定";
CM_ SG_ 2149416777 P2D_CMD2_Reserved2_09 "预留2";
CM_ SG_ 2149416777 P2D_CMD2_DCDCOutputCrrntSet_09 "电池电流设定（放正充负）
电池电流=DC低压端电流+DC高压端电流";
CM_ SG_ 2149416777 P2D_CMD2_DCDCOutputVltg_Set_09 "DCDC输出电压设定";
CM_ SG_ 2149416777 P2D_CMD2_Reserved3_09 "预留3";
CM_ SG_ 2149416777 P2D_CMD2_CommunicationState_09 "PC与DCDC通讯状态";
CM_ SG_ 2149416777 P2D_CMD2_DCDC_Fault_Clear_09 "DCDC故障清除指令";
CM_ SG_ 2149416777 P2D_CMD2_PCSOperationState_09 "PCS运行状态（预留）";
CM_ SG_ 2149416777 P2D_CMD2_DCDCLVoffControl_09 "DCDC低压下电控制";
CM_ SG_ 2149416777 P2D_CMD2_Reserved4_09 "预留4";
CM_ SG_ 2149416778 P2D_CMD2_CRC_10 "预留 （这里没必要做CRC校验吧？）";
CM_ SG_ 2149416778 P2D_CMD2_DCDCSerialNum_10 "预留（原为DCDC编号）";
CM_ SG_ 2149416778 P2D_CMD2_DCDCEnable_10 "使能DCDC命令";
CM_ SG_ 2149416778 P2D_CMD2_Reserved1_10 "预留1";
CM_ SG_ 2149416778 P2D_CMD2_DCDCWrkMdSwtch_10 "DCDC工作状态切换";
CM_ SG_ 2149416778 P2D_CMD2_DCDCWrkMdSet_10 "DCDC工作模式设定";
CM_ SG_ 2149416778 P2D_CMD2_Reserved2_10 "预留2";
CM_ SG_ 2149416778 P2D_CMD2_DCDCOutputCrrntSet_10 "电池电流设定（放正充负）
电池电流=DC低压端电流+DC高压端电流";
CM_ SG_ 2149416778 P2D_CMD2_DCDCOutputVltg_Set_10 "DCDC输出电压设定";
CM_ SG_ 2149416778 P2D_CMD2_Reserved3_10 "预留3";
CM_ SG_ 2149416778 P2D_CMD2_CommunicationState_10 "PC与DCDC通讯状态";
CM_ SG_ 2149416778 P2D_CMD2_DCDC_Fault_Clear_10 "DCDC故障清除指令";
CM_ SG_ 2149416778 P2D_CMD2_PCSOperationState_10 "PCS运行状态（预留）";
CM_ SG_ 2149416778 P2D_CMD2_DCDCLVoffControl_10 "DCDC低压下电控制";
CM_ SG_ 2149416778 P2D_CMD2_Reserved4_10 "预留4";
CM_ SG_ 2149416779 P2D_CMD2_CRC_11 "预留 （这里没必要做CRC校验吧？）";
CM_ SG_ 2149416779 P2D_CMD2_DCDCSerialNum_11 "预留（原为DCDC编号）";
CM_ SG_ 2149416779 P2D_CMD2_DCDCEnable_11 "使能DCDC命令";
CM_ SG_ 2149416779 P2D_CMD2_Reserved1_11 "预留1";
CM_ SG_ 2149416779 P2D_CMD2_DCDCWrkMdSwtch_11 "DCDC工作状态切换";
CM_ SG_ 2149416779 P2D_CMD2_DCDCWrkMdSet_11 "DCDC工作模式设定";
CM_ SG_ 2149416779 P2D_CMD2_Reserved2_11 "预留2";
CM_ SG_ 2149416779 P2D_CMD2_DCDCOutputCrrntSet_11 "电池电流设定（放正充负）
电池电流=DC低压端电流+DC高压端电流";
CM_ SG_ 2149416779 P2D_CMD2_DCDCOutputVltg_Set_11 "DCDC输出电压设定";
CM_ SG_ 2149416779 P2D_CMD2_Reserved3_11 "预留3";
CM_ SG_ 2149416779 P2D_CMD2_CommunicationState_11 "PC与DCDC通讯状态";
CM_ SG_ 2149416779 P2D_CMD2_DCDC_Fault_Clear_11 "DCDC故障清除指令";
CM_ SG_ 2149416779 P2D_CMD2_PCSOperationState_11 "PCS运行状态（预留）";
CM_ SG_ 2149416779 P2D_CMD2_DCDCLVoffControl_11 "DCDC低压下电控制";
CM_ SG_ 2149416779 P2D_CMD2_Reserved4_11 "预留4";
CM_ SG_ 2149416780 P2D_CMD2_CRC_12 "预留 （这里没必要做CRC校验吧？）";
CM_ SG_ 2149416780 P2D_CMD2_DCDCSerialNum_12 "预留（原为DCDC编号）";
CM_ SG_ 2149416780 P2D_CMD2_DCDCEnable_12 "使能DCDC命令";
CM_ SG_ 2149416780 P2D_CMD2_Reserved1_12 "预留1";
CM_ SG_ 2149416780 P2D_CMD2_DCDCWrkMdSwtch_12 "DCDC工作状态切换";
CM_ SG_ 2149416780 P2D_CMD2_DCDCWrkMdSet_12 "DCDC工作模式设定";
CM_ SG_ 2149416780 P2D_CMD2_Reserved2_12 "预留2";
CM_ SG_ 2149416780 P2D_CMD2_DCDCOutputCrrntSet_12 "电池电流设定（放正充负）
电池电流=DC低压端电流+DC高压端电流";
CM_ SG_ 2149416780 P2D_CMD2_DCDCOutputVltg_Set_12 "DCDC输出电压设定";
CM_ SG_ 2149416780 P2D_CMD2_Reserved3_12 "预留3";
CM_ SG_ 2149416780 P2D_CMD2_CommunicationState_12 "PC与DCDC通讯状态";
CM_ SG_ 2149416780 P2D_CMD2_DCDC_Fault_Clear_12 "DCDC故障清除指令";
CM_ SG_ 2149416780 P2D_CMD2_PCSOperationState_12 "PCS运行状态（预留）";
CM_ SG_ 2149416780 P2D_CMD2_DCDCLVoffControl_12 "DCDC低压下电控制";
CM_ SG_ 2149416780 P2D_CMD2_Reserved4_12 "预留4";
CM_ SG_ 2149416781 P2D_CMD2_CRC_13 "预留 （这里没必要做CRC校验吧？）";
CM_ SG_ 2149416781 P2D_CMD2_DCDCSerialNum_13 "预留（原为DCDC编号）";
CM_ SG_ 2149416781 P2D_CMD2_DCDCEnable_13 "使能DCDC命令";
CM_ SG_ 2149416781 P2D_CMD2_Reserved1_13 "预留1";
CM_ SG_ 2149416781 P2D_CMD2_DCDCWrkMdSwtch_13 "DCDC工作状态切换";
CM_ SG_ 2149416781 P2D_CMD2_DCDCWrkMdSet_13 "DCDC工作模式设定";
CM_ SG_ 2149416781 P2D_CMD2_Reserved2_13 "预留2";
CM_ SG_ 2149416781 P2D_CMD2_DCDCOutputCrrntSet_13 "电池电流设定（放正充负）
电池电流=DC低压端电流+DC高压端电流";
CM_ SG_ 2149416781 P2D_CMD2_DCDCOutputVltg_Set_13 "DCDC输出电压设定";
CM_ SG_ 2149416781 P2D_CMD2_Reserved3_13 "预留3";
CM_ SG_ 2149416781 P2D_CMD2_CommunicationState_13 "PC与DCDC通讯状态";
CM_ SG_ 2149416781 P2D_CMD2_DCDC_Fault_Clear_13 "DCDC故障清除指令";
CM_ SG_ 2149416781 P2D_CMD2_PCSOperationState_13 "PCS运行状态（预留）";
CM_ SG_ 2149416781 P2D_CMD2_DCDCLVoffControl_13 "DCDC低压下电控制";
CM_ SG_ 2149416781 P2D_CMD2_Reserved4_13 "预留4";
CM_ SG_ 2149416782 P2D_CMD2_CRC_14 "预留 （这里没必要做CRC校验吧？）";
CM_ SG_ 2149416782 P2D_CMD2_DCDCSerialNum_14 "预留（原为DCDC编号）";
CM_ SG_ 2149416782 P2D_CMD2_DCDCEnable_14 "使能DCDC命令";
CM_ SG_ 2149416782 P2D_CMD2_Reserved1_14 "预留1";
CM_ SG_ 2149416782 P2D_CMD2_DCDCWrkMdSwtch_14 "DCDC工作状态切换";
CM_ SG_ 2149416782 P2D_CMD2_DCDCWrkMdSet_14 "DCDC工作模式设定";
CM_ SG_ 2149416782 P2D_CMD2_Reserved2_14 "预留2";
CM_ SG_ 2149416782 P2D_CMD2_DCDCOutputCrrntSet_14 "电池电流设定（放正充负）
电池电流=DC低压端电流+DC高压端电流";
CM_ SG_ 2149416782 P2D_CMD2_DCDCOutputVltg_Set_14 "DCDC输出电压设定";
CM_ SG_ 2149416782 P2D_CMD2_Reserved3_14 "预留3";
CM_ SG_ 2149416782 P2D_CMD2_CommunicationState_14 "PC与DCDC通讯状态";
CM_ SG_ 2149416782 P2D_CMD2_DCDC_Fault_Clear_14 "DCDC故障清除指令";
CM_ SG_ 2149416782 P2D_CMD2_PCSOperationState_14 "PCS运行状态（预留）";
CM_ SG_ 2149416782 P2D_CMD2_DCDCLVoffControl_14 "DCDC低压下电控制";
CM_ SG_ 2149416782 P2D_CMD2_Reserved4_14 "预留4";
CM_ SG_ 2149416783 P2D_CMD2_CRC_15 "预留 （这里没必要做CRC校验吧？）";
CM_ SG_ 2149416783 P2D_CMD2_DCDCSerialNum_15 "预留（原为DCDC编号）";
CM_ SG_ 2149416783 P2D_CMD2_DCDCEnable_15 "使能DCDC命令";
CM_ SG_ 2149416783 P2D_CMD2_Reserved1_15 "预留1";
CM_ SG_ 2149416783 P2D_CMD2_DCDCWrkMdSwtch_15 "DCDC工作状态切换";
CM_ SG_ 2149416783 P2D_CMD2_DCDCWrkMdSet_15 "DCDC工作模式设定";
CM_ SG_ 2149416783 P2D_CMD2_Reserved2_15 "预留2";
CM_ SG_ 2149416783 P2D_CMD2_DCDCOutputCrrntSet_15 "电池电流设定（放正充负）
电池电流=DC低压端电流+DC高压端电流";
CM_ SG_ 2149416783 P2D_CMD2_DCDCOutputVltg_Set_15 "DCDC输出电压设定";
CM_ SG_ 2149416783 P2D_CMD2_Reserved3_15 "预留3";
CM_ SG_ 2149416783 P2D_CMD2_CommunicationState_15 "PC与DCDC通讯状态";
CM_ SG_ 2149416783 P2D_CMD2_DCDC_Fault_Clear_15 "DCDC故障清除指令";
CM_ SG_ 2149416783 P2D_CMD2_PCSOperationState_15 "PCS运行状态（预留）";
CM_ SG_ 2149416783 P2D_CMD2_DCDCLVoffControl_15 "DCDC低压下电控制";
CM_ SG_ 2149416783 P2D_CMD2_Reserved4_15 "预留4";
CM_ SG_ 2149416784 P2D_CMD2_CRC_16 "预留 （这里没必要做CRC校验吧？）";
CM_ SG_ 2149416784 P2D_CMD2_DCDCSerialNum_16 "预留（原为DCDC编号）";
CM_ SG_ 2149416784 P2D_CMD2_DCDCEnable_16 "使能DCDC命令";
CM_ SG_ 2149416784 P2D_CMD2_Reserved1_16 "预留1";
CM_ SG_ 2149416784 P2D_CMD2_DCDCWrkMdSwtch_16 "DCDC工作状态切换";
CM_ SG_ 2149416784 P2D_CMD2_DCDCWrkMdSet_16 "DCDC工作模式设定";
CM_ SG_ 2149416784 P2D_CMD2_Reserved2_16 "预留2";
CM_ SG_ 2149416784 P2D_CMD2_DCDCOutputCrrntSet_16 "电池电流设定（放正充负）
电池电流=DC低压端电流+DC高压端电流";
CM_ SG_ 2149416784 P2D_CMD2_DCDCOutputVltg_Set_16 "DCDC输出电压设定";
CM_ SG_ 2149416784 P2D_CMD2_Reserved3_16 "预留3";
CM_ SG_ 2149416784 P2D_CMD2_CommunicationState_16 "PC与DCDC通讯状态";
CM_ SG_ 2149416784 P2D_CMD2_DCDC_Fault_Clear_16 "DCDC故障清除指令";
CM_ SG_ 2149416784 P2D_CMD2_PCSOperationState_16 "PCS运行状态（预留）";
CM_ SG_ 2149416784 P2D_CMD2_DCDCLVoffControl_16 "DCDC低压下电控制";
CM_ SG_ 2149416784 P2D_CMD2_Reserved4_16 "预留4";
CM_ SG_ 2149416785 P2D_CMD2_CRC_17 "预留 （这里没必要做CRC校验吧？）";
CM_ SG_ 2149416785 P2D_CMD2_DCDCSerialNum_17 "预留（原为DCDC编号）";
CM_ SG_ 2149416785 P2D_CMD2_DCDCEnable_17 "使能DCDC命令";
CM_ SG_ 2149416785 P2D_CMD2_Reserved1_17 "预留1";
CM_ SG_ 2149416785 P2D_CMD2_DCDCWrkMdSwtch_17 "DCDC工作状态切换";
CM_ SG_ 2149416785 P2D_CMD2_DCDCWrkMdSet_17 "DCDC工作模式设定";
CM_ SG_ 2149416785 P2D_CMD2_Reserved2_17 "预留2";
CM_ SG_ 2149416785 P2D_CMD2_DCDCOutputCrrntSet_17 "电池电流设定（放正充负）
电池电流=DC低压端电流+DC高压端电流";
CM_ SG_ 2149416785 P2D_CMD2_DCDCOutputVltg_Set_17 "DCDC输出电压设定";
CM_ SG_ 2149416785 P2D_CMD2_Reserved3_17 "预留3";
CM_ SG_ 2149416785 P2D_CMD2_CommunicationState_17 "PC与DCDC通讯状态";
CM_ SG_ 2149416785 P2D_CMD2_DCDC_Fault_Clear_17 "DCDC故障清除指令";
CM_ SG_ 2149416785 P2D_CMD2_PCSOperationState_17 "PCS运行状态（预留）";
CM_ SG_ 2149416785 P2D_CMD2_DCDCLVoffControl_17 "DCDC低压下电控制";
CM_ SG_ 2149416785 P2D_CMD2_Reserved4_17 "预留4";
CM_ SG_ 2149416786 P2D_CMD2_CRC_18 "预留 （这里没必要做CRC校验吧？）";
CM_ SG_ 2149416786 P2D_CMD2_DCDCSerialNum_18 "预留（原为DCDC编号）";
CM_ SG_ 2149416786 P2D_CMD2_DCDCEnable_18 "使能DCDC命令";
CM_ SG_ 2149416786 P2D_CMD2_Reserved1_18 "预留1";
CM_ SG_ 2149416786 P2D_CMD2_DCDCWrkMdSwtch_18 "DCDC工作状态切换";
CM_ SG_ 2149416786 P2D_CMD2_DCDCWrkMdSet_18 "DCDC工作模式设定";
CM_ SG_ 2149416786 P2D_CMD2_Reserved2_18 "预留2";
CM_ SG_ 2149416786 P2D_CMD2_DCDCOutputCrrntSet_18 "电池电流设定（放正充负）
电池电流=DC低压端电流+DC高压端电流";
CM_ SG_ 2149416786 P2D_CMD2_DCDCOutputVltg_Set_18 "DCDC输出电压设定";
CM_ SG_ 2149416786 P2D_CMD2_Reserved3_18 "预留3";
CM_ SG_ 2149416786 P2D_CMD2_CommunicationState_18 "PC与DCDC通讯状态";
CM_ SG_ 2149416786 P2D_CMD2_DCDC_Fault_Clear_18 "DCDC故障清除指令";
CM_ SG_ 2149416786 P2D_CMD2_PCSOperationState_18 "PCS运行状态（预留）";
CM_ SG_ 2149416786 P2D_CMD2_DCDCLVoffControl_18 "DCDC低压下电控制";
CM_ SG_ 2149416786 P2D_CMD2_Reserved4_18 "预留4";
CM_ SG_ 2149416787 P2D_CMD2_CRC_19 "预留 （这里没必要做CRC校验吧？）";
CM_ SG_ 2149416787 P2D_CMD2_DCDCSerialNum_19 "预留（原为DCDC编号）";
CM_ SG_ 2149416787 P2D_CMD2_DCDCEnable_19 "使能DCDC命令";
CM_ SG_ 2149416787 P2D_CMD2_Reserved1_19 "预留1";
CM_ SG_ 2149416787 P2D_CMD2_DCDCWrkMdSwtch_19 "DCDC工作状态切换";
CM_ SG_ 2149416787 P2D_CMD2_DCDCWrkMdSet_19 "DCDC工作模式设定";
CM_ SG_ 2149416787 P2D_CMD2_Reserved2_19 "预留2";
CM_ SG_ 2149416787 P2D_CMD2_DCDCOutputCrrntSet_19 "电池电流设定（放正充负）
电池电流=DC低压端电流+DC高压端电流";
CM_ SG_ 2149416787 P2D_CMD2_DCDCOutputVltg_Set_19 "DCDC输出电压设定";
CM_ SG_ 2149416787 P2D_CMD2_Reserved3_19 "预留3";
CM_ SG_ 2149416787 P2D_CMD2_CommunicationState_19 "PC与DCDC通讯状态";
CM_ SG_ 2149416787 P2D_CMD2_DCDC_Fault_Clear_19 "DCDC故障清除指令";
CM_ SG_ 2149416787 P2D_CMD2_PCSOperationState_19 "PCS运行状态（预留）";
CM_ SG_ 2149416787 P2D_CMD2_DCDCLVoffControl_19 "DCDC低压下电控制";
CM_ SG_ 2149416787 P2D_CMD2_Reserved4_19 "预留4";
CM_ SG_ 2149416788 P2D_CMD2_CRC_20 "预留 （这里没必要做CRC校验吧？）";
CM_ SG_ 2149416788 P2D_CMD2_DCDCSerialNum_20 "预留（原为DCDC编号）";
CM_ SG_ 2149416788 P2D_CMD2_DCDCEnable_20 "使能DCDC命令";
CM_ SG_ 2149416788 P2D_CMD2_Reserved1_20 "预留1";
CM_ SG_ 2149416788 P2D_CMD2_DCDCWrkMdSwtch_20 "DCDC工作状态切换";
CM_ SG_ 2149416788 P2D_CMD2_DCDCWrkMdSet_20 "DCDC工作模式设定";
CM_ SG_ 2149416788 P2D_CMD2_Reserved2_20 "预留2";
CM_ SG_ 2149416788 P2D_CMD2_DCDCOutputCrrntSet_20 "电池电流设定（放正充负）
电池电流=DC低压端电流+DC高压端电流";
CM_ SG_ 2149416788 P2D_CMD2_DCDCOutputVltg_Set_20 "DCDC输出电压设定";
CM_ SG_ 2149416788 P2D_CMD2_Reserved3_20 "预留3";
CM_ SG_ 2149416788 P2D_CMD2_CommunicationState_20 "PC与DCDC通讯状态";
CM_ SG_ 2149416788 P2D_CMD2_DCDC_Fault_Clear_20 "DCDC故障清除指令";
CM_ SG_ 2149416788 P2D_CMD2_PCSOperationState_20 "PCS运行状态（预留）";
CM_ SG_ 2149416788 P2D_CMD2_DCDCLVoffControl_20 "DCDC低压下电控制";
CM_ SG_ 2149416788 P2D_CMD2_Reserved4_20 "预留4";
CM_ SG_ 2149416789 P2D_CMD2_CRC_21 "预留 （这里没必要做CRC校验吧？）";
CM_ SG_ 2149416789 P2D_CMD2_DCDCSerialNum_21 "预留（原为DCDC编号）";
CM_ SG_ 2149416789 P2D_CMD2_DCDCEnable_21 "使能DCDC命令";
CM_ SG_ 2149416789 P2D_CMD2_Reserved1_21 "预留1";
CM_ SG_ 2149416789 P2D_CMD2_DCDCWrkMdSwtch_21 "DCDC工作状态切换";
CM_ SG_ 2149416789 P2D_CMD2_DCDCWrkMdSet_21 "DCDC工作模式设定";
CM_ SG_ 2149416789 P2D_CMD2_Reserved2_21 "预留2";
CM_ SG_ 2149416789 P2D_CMD2_DCDCOutputCrrntSet_21 "电池电流设定（放正充负）
电池电流=DC低压端电流+DC高压端电流";
CM_ SG_ 2149416789 P2D_CMD2_DCDCOutputVltg_Set_21 "DCDC输出电压设定";
CM_ SG_ 2149416789 P2D_CMD2_Reserved3_21 "预留3";
CM_ SG_ 2149416789 P2D_CMD2_CommunicationState_21 "PC与DCDC通讯状态";
CM_ SG_ 2149416789 P2D_CMD2_DCDC_Fault_Clear_21 "DCDC故障清除指令";
CM_ SG_ 2149416789 P2D_CMD2_PCSOperationState_21 "PCS运行状态（预留）";
CM_ SG_ 2149416789 P2D_CMD2_DCDCLVoffControl_21 "DCDC低压下电控制";
CM_ SG_ 2149416789 P2D_CMD2_Reserved4_21 "预留4";
CM_ SG_ 2149416790 P2D_CMD2_CRC_22 "预留 （这里没必要做CRC校验吧？）";
CM_ SG_ 2149416790 P2D_CMD2_DCDCSerialNum_22 "预留（原为DCDC编号）";
CM_ SG_ 2149416790 P2D_CMD2_DCDCEnable_22 "使能DCDC命令";
CM_ SG_ 2149416790 P2D_CMD2_Reserved1_22 "预留1";
CM_ SG_ 2149416790 P2D_CMD2_DCDCWrkMdSwtch_22 "DCDC工作状态切换";
CM_ SG_ 2149416790 P2D_CMD2_DCDCWrkMdSet_22 "DCDC工作模式设定";
CM_ SG_ 2149416790 P2D_CMD2_Reserved2_22 "预留2";
CM_ SG_ 2149416790 P2D_CMD2_DCDCOutputCrrntSet_22 "电池电流设定（放正充负）
电池电流=DC低压端电流+DC高压端电流";
CM_ SG_ 2149416790 P2D_CMD2_DCDCOutputVltg_Set_22 "DCDC输出电压设定";
CM_ SG_ 2149416790 P2D_CMD2_Reserved3_22 "预留3";
CM_ SG_ 2149416790 P2D_CMD2_CommunicationState_22 "PC与DCDC通讯状态";
CM_ SG_ 2149416790 P2D_CMD2_DCDC_Fault_Clear_22 "DCDC故障清除指令";
CM_ SG_ 2149416790 P2D_CMD2_PCSOperationState_22 "PCS运行状态（预留）";
CM_ SG_ 2149416790 P2D_CMD2_DCDCLVoffControl_22 "DCDC低压下电控制";
CM_ SG_ 2149416790 P2D_CMD2_Reserved4_22 "预留4";
CM_ SG_ 2149416791 P2D_CMD2_CRC_23 "预留 （这里没必要做CRC校验吧？）";
CM_ SG_ 2149416791 P2D_CMD2_DCDCSerialNum_23 "预留（原为DCDC编号）";
CM_ SG_ 2149416791 P2D_CMD2_DCDCEnable_23 "使能DCDC命令";
CM_ SG_ 2149416791 P2D_CMD2_Reserved1_23 "预留1";
CM_ SG_ 2149416791 P2D_CMD2_DCDCWrkMdSwtch_23 "DCDC工作状态切换";
CM_ SG_ 2149416791 P2D_CMD2_DCDCWrkMdSet_23 "DCDC工作模式设定";
CM_ SG_ 2149416791 P2D_CMD2_Reserved2_23 "预留2";
CM_ SG_ 2149416791 P2D_CMD2_DCDCOutputCrrntSet_23 "电池电流设定（放正充负）
电池电流=DC低压端电流+DC高压端电流";
CM_ SG_ 2149416791 P2D_CMD2_DCDCOutputVltg_Set_23 "DCDC输出电压设定";
CM_ SG_ 2149416791 P2D_CMD2_Reserved3_23 "预留3";
CM_ SG_ 2149416791 P2D_CMD2_CommunicationState_23 "PC与DCDC通讯状态";
CM_ SG_ 2149416791 P2D_CMD2_DCDC_Fault_Clear_23 "DCDC故障清除指令";
CM_ SG_ 2149416791 P2D_CMD2_PCSOperationState_23 "PCS运行状态（预留）";
CM_ SG_ 2149416791 P2D_CMD2_DCDCLVoffControl_23 "DCDC低压下电控制";
CM_ SG_ 2149416791 P2D_CMD2_Reserved4_23 "预留4";
CM_ SG_ 2149416792 P2D_CMD2_CRC_24 "预留 （这里没必要做CRC校验吧？）";
CM_ SG_ 2149416792 P2D_CMD2_DCDCSerialNum_24 "预留（原为DCDC编号）";
CM_ SG_ 2149416792 P2D_CMD2_DCDCEnable_24 "使能DCDC命令";
CM_ SG_ 2149416792 P2D_CMD2_Reserved1_24 "预留1";
CM_ SG_ 2149416792 P2D_CMD2_DCDCWrkMdSwtch_24 "DCDC工作状态切换";
CM_ SG_ 2149416792 P2D_CMD2_DCDCWrkMdSet_24 "DCDC工作模式设定";
CM_ SG_ 2149416792 P2D_CMD2_Reserved2_24 "预留2";
CM_ SG_ 2149416792 P2D_CMD2_DCDCOutputCrrntSet_24 "电池电流设定（放正充负）
电池电流=DC低压端电流+DC高压端电流";
CM_ SG_ 2149416792 P2D_CMD2_DCDCOutputVltg_Set_24 "DCDC输出电压设定";
CM_ SG_ 2149416792 P2D_CMD2_Reserved3_24 "预留3";
CM_ SG_ 2149416792 P2D_CMD2_CommunicationState_24 "PC与DCDC通讯状态";
CM_ SG_ 2149416792 P2D_CMD2_DCDC_Fault_Clear_24 "DCDC故障清除指令";
CM_ SG_ 2149416792 P2D_CMD2_PCSOperationState_24 "PCS运行状态（预留）";
CM_ SG_ 2149416792 P2D_CMD2_DCDCLVoffControl_24 "DCDC低压下电控制";
CM_ SG_ 2149416792 P2D_CMD2_Reserved4_24 "预留4";
CM_ SG_ 2149416793 P2D_CMD2_CRC_25 "预留 （这里没必要做CRC校验吧？）";
CM_ SG_ 2149416793 P2D_CMD2_DCDCSerialNum_25 "预留（原为DCDC编号）";
CM_ SG_ 2149416793 P2D_CMD2_DCDCEnable_25 "使能DCDC命令";
CM_ SG_ 2149416793 P2D_CMD2_Reserved1_25 "预留1";
CM_ SG_ 2149416793 P2D_CMD2_DCDCWrkMdSwtch_25 "DCDC工作状态切换";
CM_ SG_ 2149416793 P2D_CMD2_DCDCWrkMdSet_25 "DCDC工作模式设定";
CM_ SG_ 2149416793 P2D_CMD2_Reserved2_25 "预留2";
CM_ SG_ 2149416793 P2D_CMD2_DCDCOutputCrrntSet_25 "电池电流设定（放正充负）
电池电流=DC低压端电流+DC高压端电流";
CM_ SG_ 2149416793 P2D_CMD2_DCDCOutputVltg_Set_25 "DCDC输出电压设定";
CM_ SG_ 2149416793 P2D_CMD2_Reserved3_25 "预留3";
CM_ SG_ 2149416793 P2D_CMD2_CommunicationState_25 "PC与DCDC通讯状态";
CM_ SG_ 2149416793 P2D_CMD2_DCDC_Fault_Clear_25 "DCDC故障清除指令";
CM_ SG_ 2149416793 P2D_CMD2_PCSOperationState_25 "PCS运行状态（预留）";
CM_ SG_ 2149416793 P2D_CMD2_DCDCLVoffControl_25 "DCDC低压下电控制";
CM_ SG_ 2149416793 P2D_CMD2_Reserved4_25 "预留4";
CM_ SG_ 2149416794 P2D_CMD2_CRC_26 "预留 （这里没必要做CRC校验吧？）";
CM_ SG_ 2149416794 P2D_CMD2_DCDCSerialNum_26 "预留（原为DCDC编号）";
CM_ SG_ 2149416794 P2D_CMD2_DCDCEnable_26 "使能DCDC命令";
CM_ SG_ 2149416794 P2D_CMD2_Reserved1_26 "预留1";
CM_ SG_ 2149416794 P2D_CMD2_DCDCWrkMdSwtch_26 "DCDC工作状态切换";
CM_ SG_ 2149416794 P2D_CMD2_DCDCWrkMdSet_26 "DCDC工作模式设定";
CM_ SG_ 2149416794 P2D_CMD2_Reserved2_26 "预留2";
CM_ SG_ 2149416794 P2D_CMD2_DCDCOutputCrrntSet_26 "电池电流设定（放正充负）
电池电流=DC低压端电流+DC高压端电流";
CM_ SG_ 2149416794 P2D_CMD2_DCDCOutputVltg_Set_26 "DCDC输出电压设定";
CM_ SG_ 2149416794 P2D_CMD2_Reserved3_26 "预留3";
CM_ SG_ 2149416794 P2D_CMD2_CommunicationState_26 "PC与DCDC通讯状态";
CM_ SG_ 2149416794 P2D_CMD2_DCDC_Fault_Clear_26 "DCDC故障清除指令";
CM_ SG_ 2149416794 P2D_CMD2_PCSOperationState_26 "PCS运行状态（预留）";
CM_ SG_ 2149416794 P2D_CMD2_DCDCLVoffControl_26 "DCDC低压下电控制";
CM_ SG_ 2149416794 P2D_CMD2_Reserved4_26 "预留4";
CM_ SG_ 2149416795 P2D_CMD2_CRC_27 "预留 （这里没必要做CRC校验吧？）";
CM_ SG_ 2149416795 P2D_CMD2_DCDCSerialNum_27 "预留（原为DCDC编号）";
CM_ SG_ 2149416795 P2D_CMD2_DCDCEnable_27 "使能DCDC命令";
CM_ SG_ 2149416795 P2D_CMD2_Reserved1_27 "预留1";
CM_ SG_ 2149416795 P2D_CMD2_DCDCWrkMdSwtch_27 "DCDC工作状态切换";
CM_ SG_ 2149416795 P2D_CMD2_DCDCWrkMdSet_27 "DCDC工作模式设定";
CM_ SG_ 2149416795 P2D_CMD2_Reserved2_27 "预留2";
CM_ SG_ 2149416795 P2D_CMD2_DCDCOutputCrrntSet_27 "电池电流设定（放正充负）
电池电流=DC低压端电流+DC高压端电流";
CM_ SG_ 2149416795 P2D_CMD2_DCDCOutputVltg_Set_27 "DCDC输出电压设定";
CM_ SG_ 2149416795 P2D_CMD2_Reserved3_27 "预留3";
CM_ SG_ 2149416795 P2D_CMD2_CommunicationState_27 "PC与DCDC通讯状态";
CM_ SG_ 2149416795 P2D_CMD2_DCDC_Fault_Clear_27 "DCDC故障清除指令";
CM_ SG_ 2149416795 P2D_CMD2_PCSOperationState_27 "PCS运行状态（预留）";
CM_ SG_ 2149416795 P2D_CMD2_DCDCLVoffControl_27 "DCDC低压下电控制";
CM_ SG_ 2149416795 P2D_CMD2_Reserved4_27 "预留4";
CM_ SG_ 2149416796 P2D_CMD2_CRC_28 "预留 （这里没必要做CRC校验吧？）";
CM_ SG_ 2149416796 P2D_CMD2_DCDCSerialNum_28 "预留（原为DCDC编号）";
CM_ SG_ 2149416796 P2D_CMD2_DCDCEnable_28 "使能DCDC命令";
CM_ SG_ 2149416796 P2D_CMD2_Reserved1_28 "预留1";
CM_ SG_ 2149416796 P2D_CMD2_DCDCWrkMdSwtch_28 "DCDC工作状态切换";
CM_ SG_ 2149416796 P2D_CMD2_DCDCWrkMdSet_28 "DCDC工作模式设定";
CM_ SG_ 2149416796 P2D_CMD2_Reserved2_28 "预留2";
CM_ SG_ 2149416796 P2D_CMD2_DCDCOutputCrrntSet_28 "电池电流设定（放正充负）
电池电流=DC低压端电流+DC高压端电流";
CM_ SG_ 2149416796 P2D_CMD2_DCDCOutputVltg_Set_28 "DCDC输出电压设定";
CM_ SG_ 2149416796 P2D_CMD2_Reserved3_28 "预留3";
CM_ SG_ 2149416796 P2D_CMD2_CommunicationState_28 "PC与DCDC通讯状态";
CM_ SG_ 2149416796 P2D_CMD2_DCDC_Fault_Clear_28 "DCDC故障清除指令";
CM_ SG_ 2149416796 P2D_CMD2_PCSOperationState_28 "PCS运行状态（预留）";
CM_ SG_ 2149416796 P2D_CMD2_DCDCLVoffControl_28 "DCDC低压下电控制";
CM_ SG_ 2149416796 P2D_CMD2_Reserved4_28 "预留4";
CM_ SG_ 2149416797 P2D_CMD2_CRC_29 "预留 （这里没必要做CRC校验吧？）";
CM_ SG_ 2149416797 P2D_CMD2_DCDCSerialNum_29 "预留（原为DCDC编号）";
CM_ SG_ 2149416797 P2D_CMD2_DCDCEnable_29 "使能DCDC命令";
CM_ SG_ 2149416797 P2D_CMD2_Reserved1_29 "预留1";
CM_ SG_ 2149416797 P2D_CMD2_DCDCWrkMdSwtch_29 "DCDC工作状态切换";
CM_ SG_ 2149416797 P2D_CMD2_DCDCWrkMdSet_29 "DCDC工作模式设定";
CM_ SG_ 2149416797 P2D_CMD2_Reserved2_29 "预留2";
CM_ SG_ 2149416797 P2D_CMD2_DCDCOutputCrrntSet_29 "电池电流设定（放正充负）
电池电流=DC低压端电流+DC高压端电流";
CM_ SG_ 2149416797 P2D_CMD2_DCDCOutputVltg_Set_29 "DCDC输出电压设定";
CM_ SG_ 2149416797 P2D_CMD2_Reserved3_29 "预留3";
CM_ SG_ 2149416797 P2D_CMD2_CommunicationState_29 "PC与DCDC通讯状态";
CM_ SG_ 2149416797 P2D_CMD2_DCDC_Fault_Clear_29 "DCDC故障清除指令";
CM_ SG_ 2149416797 P2D_CMD2_PCSOperationState_29 "PCS运行状态（预留）";
CM_ SG_ 2149416797 P2D_CMD2_DCDCLVoffControl_29 "DCDC低压下电控制";
CM_ SG_ 2149416797 P2D_CMD2_Reserved4_29 "预留4";
CM_ SG_ 2149416798 P2D_CMD2_CRC_30 "预留 （这里没必要做CRC校验吧？）";
CM_ SG_ 2149416798 P2D_CMD2_DCDCSerialNum_30 "预留（原为DCDC编号）";
CM_ SG_ 2149416798 P2D_CMD2_DCDCEnable_30 "使能DCDC命令";
CM_ SG_ 2149416798 P2D_CMD2_Reserved1_30 "预留1";
CM_ SG_ 2149416798 P2D_CMD2_DCDCWrkMdSwtch_30 "DCDC工作状态切换";
CM_ SG_ 2149416798 P2D_CMD2_DCDCWrkMdSet_30 "DCDC工作模式设定";
CM_ SG_ 2149416798 P2D_CMD2_Reserved2_30 "预留2";
CM_ SG_ 2149416798 P2D_CMD2_DCDCOutputCrrntSet_30 "电池电流设定（放正充负）
电池电流=DC低压端电流+DC高压端电流";
CM_ SG_ 2149416798 P2D_CMD2_DCDCOutputVltg_Set_30 "DCDC输出电压设定";
CM_ SG_ 2149416798 P2D_CMD2_Reserved3_30 "预留3";
CM_ SG_ 2149416798 P2D_CMD2_CommunicationState_30 "PC与DCDC通讯状态";
CM_ SG_ 2149416798 P2D_CMD2_DCDC_Fault_Clear_30 "DCDC故障清除指令";
CM_ SG_ 2149416798 P2D_CMD2_PCSOperationState_30 "PCS运行状态（预留）";
CM_ SG_ 2149416798 P2D_CMD2_DCDCLVoffControl_30 "DCDC低压下电控制";
CM_ SG_ 2149416798 P2D_CMD2_Reserved4_30 "预留4";
CM_ SG_ 2149416799 P2D_CMD2_CRC_31 "预留 （这里没必要做CRC校验吧？）";
CM_ SG_ 2149416799 P2D_CMD2_DCDCSerialNum_31 "预留（原为DCDC编号）";
CM_ SG_ 2149416799 P2D_CMD2_DCDCEnable_31 "使能DCDC命令";
CM_ SG_ 2149416799 P2D_CMD2_Reserved1_31 "预留1";
CM_ SG_ 2149416799 P2D_CMD2_DCDCWrkMdSwtch_31 "DCDC工作状态切换";
CM_ SG_ 2149416799 P2D_CMD2_DCDCWrkMdSet_31 "DCDC工作模式设定";
CM_ SG_ 2149416799 P2D_CMD2_Reserved2_31 "预留2";
CM_ SG_ 2149416799 P2D_CMD2_DCDCOutputCrrntSet_31 "电池电流设定（放正充负）
电池电流=DC低压端电流+DC高压端电流";
CM_ SG_ 2149416799 P2D_CMD2_DCDCOutputVltg_Set_31 "DCDC输出电压设定";
CM_ SG_ 2149416799 P2D_CMD2_Reserved3_31 "预留3";
CM_ SG_ 2149416799 P2D_CMD2_CommunicationState_31 "PC与DCDC通讯状态";
CM_ SG_ 2149416799 P2D_CMD2_DCDC_Fault_Clear_31 "DCDC故障清除指令";
CM_ SG_ 2149416799 P2D_CMD2_PCSOperationState_31 "PCS运行状态（预留）";
CM_ SG_ 2149416799 P2D_CMD2_DCDCLVoffControl_31 "DCDC低压下电控制";
CM_ SG_ 2149416799 P2D_CMD2_Reserved4_31 "预留4";
CM_ SG_ 2149416800 P2D_CMD2_CRC_32 "预留 （这里没必要做CRC校验吧？）";
CM_ SG_ 2149416800 P2D_CMD2_DCDCSerialNum_32 "预留（原为DCDC编号）";
CM_ SG_ 2149416800 P2D_CMD2_DCDCEnable_32 "使能DCDC命令";
CM_ SG_ 2149416800 P2D_CMD2_Reserved1_32 "预留1";
CM_ SG_ 2149416800 P2D_CMD2_DCDCWrkMdSwtch_32 "DCDC工作状态切换";
CM_ SG_ 2149416800 P2D_CMD2_DCDCWrkMdSet_32 "DCDC工作模式设定";
CM_ SG_ 2149416800 P2D_CMD2_Reserved2_32 "预留2";
CM_ SG_ 2149416800 P2D_CMD2_DCDCOutputCrrntSet_32 "电池电流设定（放正充负）
电池电流=DC低压端电流+DC高压端电流";
CM_ SG_ 2149416800 P2D_CMD2_DCDCOutputVltg_Set_32 "DCDC输出电压设定";
CM_ SG_ 2149416800 P2D_CMD2_Reserved3_32 "预留3";
CM_ SG_ 2149416800 P2D_CMD2_CommunicationState_32 "PC与DCDC通讯状态";
CM_ SG_ 2149416800 P2D_CMD2_DCDC_Fault_Clear_32 "DCDC故障清除指令";
CM_ SG_ 2149416800 P2D_CMD2_PCSOperationState_32 "PCS运行状态（预留）";
CM_ SG_ 2149416800 P2D_CMD2_DCDCLVoffControl_32 "DCDC低压下电控制";
CM_ SG_ 2149416800 P2D_CMD2_Reserved4_32 "预留4";
CM_ SG_ 2149416801 P2D_CMD2_CRC_33 "预留 （这里没必要做CRC校验吧？）";
CM_ SG_ 2149416801 P2D_CMD2_DCDCSerialNum_33 "预留（原为DCDC编号）";
CM_ SG_ 2149416801 P2D_CMD2_DCDCEnable_33 "使能DCDC命令";
CM_ SG_ 2149416801 P2D_CMD2_Reserved1_33 "预留1";
CM_ SG_ 2149416801 P2D_CMD2_DCDCWrkMdSwtch_33 "DCDC工作状态切换";
CM_ SG_ 2149416801 P2D_CMD2_DCDCWrkMdSet_33 "DCDC工作模式设定";
CM_ SG_ 2149416801 P2D_CMD2_Reserved2_33 "预留2";
CM_ SG_ 2149416801 P2D_CMD2_DCDCOutputCrrntSet_33 "电池电流设定（放正充负）
电池电流=DC低压端电流+DC高压端电流";
CM_ SG_ 2149416801 P2D_CMD2_DCDCOutputVltg_Set_33 "DCDC输出电压设定";
CM_ SG_ 2149416801 P2D_CMD2_Reserved3_33 "预留3";
CM_ SG_ 2149416801 P2D_CMD2_CommunicationState_33 "PC与DCDC通讯状态";
CM_ SG_ 2149416801 P2D_CMD2_DCDC_Fault_Clear_33 "DCDC故障清除指令";
CM_ SG_ 2149416801 P2D_CMD2_PCSOperationState_33 "PCS运行状态（预留）";
CM_ SG_ 2149416801 P2D_CMD2_DCDCLVoffControl_33 "DCDC低压下电控制";
CM_ SG_ 2149416801 P2D_CMD2_Reserved4_33 "预留4";
CM_ SG_ 2149416802 P2D_CMD2_CRC_34 "预留 （这里没必要做CRC校验吧？）";
CM_ SG_ 2149416802 P2D_CMD2_DCDCSerialNum_34 "预留（原为DCDC编号）";
CM_ SG_ 2149416802 P2D_CMD2_DCDCEnable_34 "使能DCDC命令";
CM_ SG_ 2149416802 P2D_CMD2_Reserved1_34 "预留1";
CM_ SG_ 2149416802 P2D_CMD2_DCDCWrkMdSwtch_34 "DCDC工作状态切换";
CM_ SG_ 2149416802 P2D_CMD2_DCDCWrkMdSet_34 "DCDC工作模式设定";
CM_ SG_ 2149416802 P2D_CMD2_Reserved2_34 "预留2";
CM_ SG_ 2149416802 P2D_CMD2_DCDCOutputCrrntSet_34 "电池电流设定（放正充负）
电池电流=DC低压端电流+DC高压端电流";
CM_ SG_ 2149416802 P2D_CMD2_DCDCOutputVltg_Set_34 "DCDC输出电压设定";
CM_ SG_ 2149416802 P2D_CMD2_Reserved3_34 "预留3";
CM_ SG_ 2149416802 P2D_CMD2_CommunicationState_34 "PC与DCDC通讯状态";
CM_ SG_ 2149416802 P2D_CMD2_DCDC_Fault_Clear_34 "DCDC故障清除指令";
CM_ SG_ 2149416802 P2D_CMD2_PCSOperationState_34 "PCS运行状态（预留）";
CM_ SG_ 2149416802 P2D_CMD2_DCDCLVoffControl_34 "DCDC低压下电控制";
CM_ SG_ 2149416802 P2D_CMD2_Reserved4_34 "预留4";
CM_ SG_ 2149416803 P2D_CMD2_CRC_35 "预留 （这里没必要做CRC校验吧？）";
CM_ SG_ 2149416803 P2D_CMD2_DCDCSerialNum_35 "预留（原为DCDC编号）";
CM_ SG_ 2149416803 P2D_CMD2_DCDCEnable_35 "使能DCDC命令";
CM_ SG_ 2149416803 P2D_CMD2_Reserved1_35 "预留1";
CM_ SG_ 2149416803 P2D_CMD2_DCDCWrkMdSwtch_35 "DCDC工作状态切换";
CM_ SG_ 2149416803 P2D_CMD2_DCDCWrkMdSet_35 "DCDC工作模式设定";
CM_ SG_ 2149416803 P2D_CMD2_Reserved2_35 "预留2";
CM_ SG_ 2149416803 P2D_CMD2_DCDCOutputCrrntSet_35 "电池电流设定（放正充负）
电池电流=DC低压端电流+DC高压端电流";
CM_ SG_ 2149416803 P2D_CMD2_DCDCOutputVltg_Set_35 "DCDC输出电压设定";
CM_ SG_ 2149416803 P2D_CMD2_Reserved3_35 "预留3";
CM_ SG_ 2149416803 P2D_CMD2_CommunicationState_35 "PC与DCDC通讯状态";
CM_ SG_ 2149416803 P2D_CMD2_DCDC_Fault_Clear_35 "DCDC故障清除指令";
CM_ SG_ 2149416803 P2D_CMD2_PCSOperationState_35 "PCS运行状态（预留）";
CM_ SG_ 2149416803 P2D_CMD2_DCDCLVoffControl_35 "DCDC低压下电控制";
CM_ SG_ 2149416803 P2D_CMD2_Reserved4_35 "预留4";
CM_ SG_ 2149416804 P2D_CMD2_CRC_36 "预留 （这里没必要做CRC校验吧？）";
CM_ SG_ 2149416804 P2D_CMD2_DCDCSerialNum_36 "预留（原为DCDC编号）";
CM_ SG_ 2149416804 P2D_CMD2_DCDCEnable_36 "使能DCDC命令";
CM_ SG_ 2149416804 P2D_CMD2_Reserved1_36 "预留1";
CM_ SG_ 2149416804 P2D_CMD2_DCDCWrkMdSwtch_36 "DCDC工作状态切换";
CM_ SG_ 2149416804 P2D_CMD2_DCDCWrkMdSet_36 "DCDC工作模式设定";
CM_ SG_ 2149416804 P2D_CMD2_Reserved2_36 "预留2";
CM_ SG_ 2149416804 P2D_CMD2_DCDCOutputCrrntSet_36 "电池电流设定（放正充负）
电池电流=DC低压端电流+DC高压端电流";
CM_ SG_ 2149416804 P2D_CMD2_DCDCOutputVltg_Set_36 "DCDC输出电压设定";
CM_ SG_ 2149416804 P2D_CMD2_Reserved3_36 "预留3";
CM_ SG_ 2149416804 P2D_CMD2_CommunicationState_36 "PC与DCDC通讯状态";
CM_ SG_ 2149416804 P2D_CMD2_DCDC_Fault_Clear_36 "DCDC故障清除指令";
CM_ SG_ 2149416804 P2D_CMD2_PCSOperationState_36 "PCS运行状态（预留）";
CM_ SG_ 2149416804 P2D_CMD2_DCDCLVoffControl_36 "DCDC低压下电控制";
CM_ SG_ 2149416804 P2D_CMD2_Reserved4_36 "预留4";
CM_ SG_ 2149416805 P2D_CMD2_CRC_37 "预留 （这里没必要做CRC校验吧？）";
CM_ SG_ 2149416805 P2D_CMD2_DCDCSerialNum_37 "预留（原为DCDC编号）";
CM_ SG_ 2149416805 P2D_CMD2_DCDCEnable_37 "使能DCDC命令";
CM_ SG_ 2149416805 P2D_CMD2_Reserved1_37 "预留1";
CM_ SG_ 2149416805 P2D_CMD2_DCDCWrkMdSwtch_37 "DCDC工作状态切换";
CM_ SG_ 2149416805 P2D_CMD2_DCDCWrkMdSet_37 "DCDC工作模式设定";
CM_ SG_ 2149416805 P2D_CMD2_Reserved2_37 "预留2";
CM_ SG_ 2149416805 P2D_CMD2_DCDCOutputCrrntSet_37 "电池电流设定（放正充负）
电池电流=DC低压端电流+DC高压端电流";
CM_ SG_ 2149416805 P2D_CMD2_DCDCOutputVltg_Set_37 "DCDC输出电压设定";
CM_ SG_ 2149416805 P2D_CMD2_Reserved3_37 "预留3";
CM_ SG_ 2149416805 P2D_CMD2_CommunicationState_37 "PC与DCDC通讯状态";
CM_ SG_ 2149416805 P2D_CMD2_DCDC_Fault_Clear_37 "DCDC故障清除指令";
CM_ SG_ 2149416805 P2D_CMD2_PCSOperationState_37 "PCS运行状态（预留）";
CM_ SG_ 2149416805 P2D_CMD2_DCDCLVoffControl_37 "DCDC低压下电控制";
CM_ SG_ 2149416805 P2D_CMD2_Reserved4_37 "预留4";
CM_ SG_ 2149416806 P2D_CMD2_CRC_38 "预留 （这里没必要做CRC校验吧？）";
CM_ SG_ 2149416806 P2D_CMD2_DCDCSerialNum_38 "预留（原为DCDC编号）";
CM_ SG_ 2149416806 P2D_CMD2_DCDCEnable_38 "使能DCDC命令";
CM_ SG_ 2149416806 P2D_CMD2_Reserved1_38 "预留1";
CM_ SG_ 2149416806 P2D_CMD2_DCDCWrkMdSwtch_38 "DCDC工作状态切换";
CM_ SG_ 2149416806 P2D_CMD2_DCDCWrkMdSet_38 "DCDC工作模式设定";
CM_ SG_ 2149416806 P2D_CMD2_Reserved2_38 "预留2";
CM_ SG_ 2149416806 P2D_CMD2_DCDCOutputCrrntSet_38 "电池电流设定（放正充负）
电池电流=DC低压端电流+DC高压端电流";
CM_ SG_ 2149416806 P2D_CMD2_DCDCOutputVltg_Set_38 "DCDC输出电压设定";
CM_ SG_ 2149416806 P2D_CMD2_Reserved3_38 "预留3";
CM_ SG_ 2149416806 P2D_CMD2_CommunicationState_38 "PC与DCDC通讯状态";
CM_ SG_ 2149416806 P2D_CMD2_DCDC_Fault_Clear_38 "DCDC故障清除指令";
CM_ SG_ 2149416806 P2D_CMD2_PCSOperationState_38 "PCS运行状态（预留）";
CM_ SG_ 2149416806 P2D_CMD2_DCDCLVoffControl_38 "DCDC低压下电控制";
CM_ SG_ 2149416806 P2D_CMD2_Reserved4_38 "预留4";
CM_ SG_ 2149416807 P2D_CMD2_CRC_39 "预留 （这里没必要做CRC校验吧？）";
CM_ SG_ 2149416807 P2D_CMD2_DCDCSerialNum_39 "预留（原为DCDC编号）";
CM_ SG_ 2149416807 P2D_CMD2_DCDCEnable_39 "使能DCDC命令";
CM_ SG_ 2149416807 P2D_CMD2_Reserved1_39 "预留1";
CM_ SG_ 2149416807 P2D_CMD2_DCDCWrkMdSwtch_39 "DCDC工作状态切换";
CM_ SG_ 2149416807 P2D_CMD2_DCDCWrkMdSet_39 "DCDC工作模式设定";
CM_ SG_ 2149416807 P2D_CMD2_Reserved2_39 "预留2";
CM_ SG_ 2149416807 P2D_CMD2_DCDCOutputCrrntSet_39 "电池电流设定（放正充负）
电池电流=DC低压端电流+DC高压端电流";
CM_ SG_ 2149416807 P2D_CMD2_DCDCOutputVltg_Set_39 "DCDC输出电压设定";
CM_ SG_ 2149416807 P2D_CMD2_Reserved3_39 "预留3";
CM_ SG_ 2149416807 P2D_CMD2_CommunicationState_39 "PC与DCDC通讯状态";
CM_ SG_ 2149416807 P2D_CMD2_DCDC_Fault_Clear_39 "DCDC故障清除指令";
CM_ SG_ 2149416807 P2D_CMD2_PCSOperationState_39 "PCS运行状态（预留）";
CM_ SG_ 2149416807 P2D_CMD2_DCDCLVoffControl_39 "DCDC低压下电控制";
CM_ SG_ 2149416807 P2D_CMD2_Reserved4_39 "预留4";
CM_ SG_ 2149416808 P2D_CMD2_CRC_40 "预留 （这里没必要做CRC校验吧？）";
CM_ SG_ 2149416808 P2D_CMD2_DCDCSerialNum_40 "预留（原为DCDC编号）";
CM_ SG_ 2149416808 P2D_CMD2_DCDCEnable_40 "使能DCDC命令";
CM_ SG_ 2149416808 P2D_CMD2_Reserved1_40 "预留1";
CM_ SG_ 2149416808 P2D_CMD2_DCDCWrkMdSwtch_40 "DCDC工作状态切换";
CM_ SG_ 2149416808 P2D_CMD2_DCDCWrkMdSet_40 "DCDC工作模式设定";
CM_ SG_ 2149416808 P2D_CMD2_Reserved2_40 "预留2";
CM_ SG_ 2149416808 P2D_CMD2_DCDCOutputCrrntSet_40 "电池电流设定（放正充负）
电池电流=DC低压端电流+DC高压端电流";
CM_ SG_ 2149416808 P2D_CMD2_DCDCOutputVltg_Set_40 "DCDC输出电压设定";
CM_ SG_ 2149416808 P2D_CMD2_Reserved3_40 "预留3";
CM_ SG_ 2149416808 P2D_CMD2_CommunicationState_40 "PC与DCDC通讯状态";
CM_ SG_ 2149416808 P2D_CMD2_DCDC_Fault_Clear_40 "DCDC故障清除指令";
CM_ SG_ 2149416808 P2D_CMD2_PCSOperationState_40 "PCS运行状态（预留）";
CM_ SG_ 2149416808 P2D_CMD2_DCDCLVoffControl_40 "DCDC低压下电控制";
CM_ SG_ 2149416808 P2D_CMD2_Reserved4_40 "预留4";
CM_ SG_ 2149416809 P2D_CMD2_CRC_41 "预留 （这里没必要做CRC校验吧？）";
CM_ SG_ 2149416809 P2D_CMD2_DCDCSerialNum_41 "预留（原为DCDC编号）";
CM_ SG_ 2149416809 P2D_CMD2_DCDCEnable_41 "使能DCDC命令";
CM_ SG_ 2149416809 P2D_CMD2_Reserved1_41 "预留1";
CM_ SG_ 2149416809 P2D_CMD2_DCDCWrkMdSwtch_41 "DCDC工作状态切换";
CM_ SG_ 2149416809 P2D_CMD2_DCDCWrkMdSet_41 "DCDC工作模式设定";
CM_ SG_ 2149416809 P2D_CMD2_Reserved2_41 "预留2";
CM_ SG_ 2149416809 P2D_CMD2_DCDCOutputCrrntSet_41 "电池电流设定（放正充负）
电池电流=DC低压端电流+DC高压端电流";
CM_ SG_ 2149416809 P2D_CMD2_DCDCOutputVltg_Set_41 "DCDC输出电压设定";
CM_ SG_ 2149416809 P2D_CMD2_Reserved3_41 "预留3";
CM_ SG_ 2149416809 P2D_CMD2_CommunicationState_41 "PC与DCDC通讯状态";
CM_ SG_ 2149416809 P2D_CMD2_DCDC_Fault_Clear_41 "DCDC故障清除指令";
CM_ SG_ 2149416809 P2D_CMD2_PCSOperationState_41 "PCS运行状态（预留）";
CM_ SG_ 2149416809 P2D_CMD2_DCDCLVoffControl_41 "DCDC低压下电控制";
CM_ SG_ 2149416809 P2D_CMD2_Reserved4_41 "预留4";
CM_ SG_ 2149416810 P2D_CMD2_CRC_42 "预留 （这里没必要做CRC校验吧？）";
CM_ SG_ 2149416810 P2D_CMD2_DCDCSerialNum_42 "预留（原为DCDC编号）";
CM_ SG_ 2149416810 P2D_CMD2_DCDCEnable_42 "使能DCDC命令";
CM_ SG_ 2149416810 P2D_CMD2_Reserved1_42 "预留1";
CM_ SG_ 2149416810 P2D_CMD2_DCDCWrkMdSwtch_42 "DCDC工作状态切换";
CM_ SG_ 2149416810 P2D_CMD2_DCDCWrkMdSet_42 "DCDC工作模式设定";
CM_ SG_ 2149416810 P2D_CMD2_Reserved2_42 "预留2";
CM_ SG_ 2149416810 P2D_CMD2_DCDCOutputCrrntSet_42 "电池电流设定（放正充负）
电池电流=DC低压端电流+DC高压端电流";
CM_ SG_ 2149416810 P2D_CMD2_DCDCOutputVltg_Set_42 "DCDC输出电压设定";
CM_ SG_ 2149416810 P2D_CMD2_Reserved3_42 "预留3";
CM_ SG_ 2149416810 P2D_CMD2_CommunicationState_42 "PC与DCDC通讯状态";
CM_ SG_ 2149416810 P2D_CMD2_DCDC_Fault_Clear_42 "DCDC故障清除指令";
CM_ SG_ 2149416810 P2D_CMD2_PCSOperationState_42 "PCS运行状态（预留）";
CM_ SG_ 2149416810 P2D_CMD2_DCDCLVoffControl_42 "DCDC低压下电控制";
CM_ SG_ 2149416810 P2D_CMD2_Reserved4_42 "预留4";
CM_ SG_ 2149416811 P2D_CMD2_CRC_43 "预留 （这里没必要做CRC校验吧？）";
CM_ SG_ 2149416811 P2D_CMD2_DCDCSerialNum_43 "预留（原为DCDC编号）";
CM_ SG_ 2149416811 P2D_CMD2_DCDCEnable_43 "使能DCDC命令";
CM_ SG_ 2149416811 P2D_CMD2_Reserved1_43 "预留1";
CM_ SG_ 2149416811 P2D_CMD2_DCDCWrkMdSwtch_43 "DCDC工作状态切换";
CM_ SG_ 2149416811 P2D_CMD2_DCDCWrkMdSet_43 "DCDC工作模式设定";
CM_ SG_ 2149416811 P2D_CMD2_Reserved2_43 "预留2";
CM_ SG_ 2149416811 P2D_CMD2_DCDCOutputCrrntSet_43 "电池电流设定（放正充负）
电池电流=DC低压端电流+DC高压端电流";
CM_ SG_ 2149416811 P2D_CMD2_DCDCOutputVltg_Set_43 "DCDC输出电压设定";
CM_ SG_ 2149416811 P2D_CMD2_Reserved3_43 "预留3";
CM_ SG_ 2149416811 P2D_CMD2_CommunicationState_43 "PC与DCDC通讯状态";
CM_ SG_ 2149416811 P2D_CMD2_DCDC_Fault_Clear_43 "DCDC故障清除指令";
CM_ SG_ 2149416811 P2D_CMD2_PCSOperationState_43 "PCS运行状态（预留）";
CM_ SG_ 2149416811 P2D_CMD2_DCDCLVoffControl_43 "DCDC低压下电控制";
CM_ SG_ 2149416811 P2D_CMD2_Reserved4_43 "预留4";
CM_ SG_ 2149416812 P2D_CMD2_CRC_44 "预留 （这里没必要做CRC校验吧？）";
CM_ SG_ 2149416812 P2D_CMD2_DCDCSerialNum_44 "预留（原为DCDC编号）";
CM_ SG_ 2149416812 P2D_CMD2_DCDCEnable_44 "使能DCDC命令";
CM_ SG_ 2149416812 P2D_CMD2_Reserved1_44 "预留1";
CM_ SG_ 2149416812 P2D_CMD2_DCDCWrkMdSwtch_44 "DCDC工作状态切换";
CM_ SG_ 2149416812 P2D_CMD2_DCDCWrkMdSet_44 "DCDC工作模式设定";
CM_ SG_ 2149416812 P2D_CMD2_Reserved2_44 "预留2";
CM_ SG_ 2149416812 P2D_CMD2_DCDCOutputCrrntSet_44 "电池电流设定（放正充负）
电池电流=DC低压端电流+DC高压端电流";
CM_ SG_ 2149416812 P2D_CMD2_DCDCOutputVltg_Set_44 "DCDC输出电压设定";
CM_ SG_ 2149416812 P2D_CMD2_Reserved3_44 "预留3";
CM_ SG_ 2149416812 P2D_CMD2_CommunicationState_44 "PC与DCDC通讯状态";
CM_ SG_ 2149416812 P2D_CMD2_DCDC_Fault_Clear_44 "DCDC故障清除指令";
CM_ SG_ 2149416812 P2D_CMD2_PCSOperationState_44 "PCS运行状态（预留）";
CM_ SG_ 2149416812 P2D_CMD2_DCDCLVoffControl_44 "DCDC低压下电控制";
CM_ SG_ 2149416812 P2D_CMD2_Reserved4_44 "预留4";
CM_ SG_ 2149416813 P2D_CMD2_CRC_45 "预留 （这里没必要做CRC校验吧？）";
CM_ SG_ 2149416813 P2D_CMD2_DCDCSerialNum_45 "预留（原为DCDC编号）";
CM_ SG_ 2149416813 P2D_CMD2_DCDCEnable_45 "使能DCDC命令";
CM_ SG_ 2149416813 P2D_CMD2_Reserved1_45 "预留1";
CM_ SG_ 2149416813 P2D_CMD2_DCDCWrkMdSwtch_45 "DCDC工作状态切换";
CM_ SG_ 2149416813 P2D_CMD2_DCDCWrkMdSet_45 "DCDC工作模式设定";
CM_ SG_ 2149416813 P2D_CMD2_Reserved2_45 "预留2";
CM_ SG_ 2149416813 P2D_CMD2_DCDCOutputCrrntSet_45 "电池电流设定（放正充负）
电池电流=DC低压端电流+DC高压端电流";
CM_ SG_ 2149416813 P2D_CMD2_DCDCOutputVltg_Set_45 "DCDC输出电压设定";
CM_ SG_ 2149416813 P2D_CMD2_Reserved3_45 "预留3";
CM_ SG_ 2149416813 P2D_CMD2_CommunicationState_45 "PC与DCDC通讯状态";
CM_ SG_ 2149416813 P2D_CMD2_DCDC_Fault_Clear_45 "DCDC故障清除指令";
CM_ SG_ 2149416813 P2D_CMD2_PCSOperationState_45 "PCS运行状态（预留）";
CM_ SG_ 2149416813 P2D_CMD2_DCDCLVoffControl_45 "DCDC低压下电控制";
CM_ SG_ 2149416813 P2D_CMD2_Reserved4_45 "预留4";
CM_ SG_ 2149416814 P2D_CMD2_CRC_46 "预留 （这里没必要做CRC校验吧？）";
CM_ SG_ 2149416814 P2D_CMD2_DCDCSerialNum_46 "预留（原为DCDC编号）";
CM_ SG_ 2149416814 P2D_CMD2_DCDCEnable_46 "使能DCDC命令";
CM_ SG_ 2149416814 P2D_CMD2_Reserved1_46 "预留1";
CM_ SG_ 2149416814 P2D_CMD2_DCDCWrkMdSwtch_46 "DCDC工作状态切换";
CM_ SG_ 2149416814 P2D_CMD2_DCDCWrkMdSet_46 "DCDC工作模式设定";
CM_ SG_ 2149416814 P2D_CMD2_Reserved2_46 "预留2";
CM_ SG_ 2149416814 P2D_CMD2_DCDCOutputCrrntSet_46 "电池电流设定（放正充负）
电池电流=DC低压端电流+DC高压端电流";
CM_ SG_ 2149416814 P2D_CMD2_DCDCOutputVltg_Set_46 "DCDC输出电压设定";
CM_ SG_ 2149416814 P2D_CMD2_Reserved3_46 "预留3";
CM_ SG_ 2149416814 P2D_CMD2_CommunicationState_46 "PC与DCDC通讯状态";
CM_ SG_ 2149416814 P2D_CMD2_DCDC_Fault_Clear_46 "DCDC故障清除指令";
CM_ SG_ 2149416814 P2D_CMD2_PCSOperationState_46 "PCS运行状态（预留）";
CM_ SG_ 2149416814 P2D_CMD2_DCDCLVoffControl_46 "DCDC低压下电控制";
CM_ SG_ 2149416814 P2D_CMD2_Reserved4_46 "预留4";
CM_ SG_ 2149416815 P2D_CMD2_CRC_47 "预留 （这里没必要做CRC校验吧？）";
CM_ SG_ 2149416815 P2D_CMD2_DCDCSerialNum_47 "预留（原为DCDC编号）";
CM_ SG_ 2149416815 P2D_CMD2_DCDCEnable_47 "使能DCDC命令";
CM_ SG_ 2149416815 P2D_CMD2_Reserved1_47 "预留1";
CM_ SG_ 2149416815 P2D_CMD2_DCDCWrkMdSwtch_47 "DCDC工作状态切换";
CM_ SG_ 2149416815 P2D_CMD2_DCDCWrkMdSet_47 "DCDC工作模式设定";
CM_ SG_ 2149416815 P2D_CMD2_Reserved2_47 "预留2";
CM_ SG_ 2149416815 P2D_CMD2_DCDCOutputCrrntSet_47 "电池电流设定（放正充负）
电池电流=DC低压端电流+DC高压端电流";
CM_ SG_ 2149416815 P2D_CMD2_DCDCOutputVltg_Set_47 "DCDC输出电压设定";
CM_ SG_ 2149416815 P2D_CMD2_Reserved3_47 "预留3";
CM_ SG_ 2149416815 P2D_CMD2_CommunicationState_47 "PC与DCDC通讯状态";
CM_ SG_ 2149416815 P2D_CMD2_DCDC_Fault_Clear_47 "DCDC故障清除指令";
CM_ SG_ 2149416815 P2D_CMD2_PCSOperationState_47 "PCS运行状态（预留）";
CM_ SG_ 2149416815 P2D_CMD2_DCDCLVoffControl_47 "DCDC低压下电控制";
CM_ SG_ 2149416815 P2D_CMD2_Reserved4_47 "预留4";
CM_ SG_ 2149416816 P2D_CMD2_CRC_48 "预留 （这里没必要做CRC校验吧？）";
CM_ SG_ 2149416816 P2D_CMD2_DCDCSerialNum_48 "预留（原为DCDC编号）";
CM_ SG_ 2149416816 P2D_CMD2_DCDCEnable_48 "使能DCDC命令";
CM_ SG_ 2149416816 P2D_CMD2_Reserved1_48 "预留1";
CM_ SG_ 2149416816 P2D_CMD2_DCDCWrkMdSwtch_48 "DCDC工作状态切换";
CM_ SG_ 2149416816 P2D_CMD2_DCDCWrkMdSet_48 "DCDC工作模式设定";
CM_ SG_ 2149416816 P2D_CMD2_Reserved2_48 "预留2";
CM_ SG_ 2149416816 P2D_CMD2_DCDCOutputCrrntSet_48 "电池电流设定（放正充负）
电池电流=DC低压端电流+DC高压端电流";
CM_ SG_ 2149416816 P2D_CMD2_DCDCOutputVltg_Set_48 "DCDC输出电压设定";
CM_ SG_ 2149416816 P2D_CMD2_Reserved3_48 "预留3";
CM_ SG_ 2149416816 P2D_CMD2_CommunicationState_48 "PC与DCDC通讯状态";
CM_ SG_ 2149416816 P2D_CMD2_DCDC_Fault_Clear_48 "DCDC故障清除指令";
CM_ SG_ 2149416816 P2D_CMD2_PCSOperationState_48 "PCS运行状态（预留）";
CM_ SG_ 2149416816 P2D_CMD2_DCDCLVoffControl_48 "DCDC低压下电控制";
CM_ SG_ 2149416816 P2D_CMD2_Reserved4_48 "预留4";
CM_ SG_ 2149416817 P2D_CMD2_CRC_49 "预留 （这里没必要做CRC校验吧？）";
CM_ SG_ 2149416817 P2D_CMD2_DCDCSerialNum_49 "预留（原为DCDC编号）";
CM_ SG_ 2149416817 P2D_CMD2_DCDCEnable_49 "使能DCDC命令";
CM_ SG_ 2149416817 P2D_CMD2_Reserved1_49 "预留1";
CM_ SG_ 2149416817 P2D_CMD2_DCDCWrkMdSwtch_49 "DCDC工作状态切换";
CM_ SG_ 2149416817 P2D_CMD2_DCDCWrkMdSet_49 "DCDC工作模式设定";
CM_ SG_ 2149416817 P2D_CMD2_Reserved2_49 "预留2";
CM_ SG_ 2149416817 P2D_CMD2_DCDCOutputCrrntSet_49 "电池电流设定（放正充负）
电池电流=DC低压端电流+DC高压端电流";
CM_ SG_ 2149416817 P2D_CMD2_DCDCOutputVltg_Set_49 "DCDC输出电压设定";
CM_ SG_ 2149416817 P2D_CMD2_Reserved3_49 "预留3";
CM_ SG_ 2149416817 P2D_CMD2_CommunicationState_49 "PC与DCDC通讯状态";
CM_ SG_ 2149416817 P2D_CMD2_DCDC_Fault_Clear_49 "DCDC故障清除指令";
CM_ SG_ 2149416817 P2D_CMD2_PCSOperationState_49 "PCS运行状态（预留）";
CM_ SG_ 2149416817 P2D_CMD2_DCDCLVoffControl_49 "DCDC低压下电控制";
CM_ SG_ 2149416817 P2D_CMD2_Reserved4_49 "预留4";
CM_ SG_ 2149416818 P2D_CMD2_CRC_50 "预留 （这里没必要做CRC校验吧？）";
CM_ SG_ 2149416818 P2D_CMD2_DCDCSerialNum_50 "预留（原为DCDC编号）";
CM_ SG_ 2149416818 P2D_CMD2_DCDCEnable_50 "使能DCDC命令";
CM_ SG_ 2149416818 P2D_CMD2_Reserved1_50 "预留1";
CM_ SG_ 2149416818 P2D_CMD2_DCDCWrkMdSwtch_50 "DCDC工作状态切换";
CM_ SG_ 2149416818 P2D_CMD2_DCDCWrkMdSet_50 "DCDC工作模式设定";
CM_ SG_ 2149416818 P2D_CMD2_Reserved2_50 "预留2";
CM_ SG_ 2149416818 P2D_CMD2_DCDCOutputCrrntSet_50 "电池电流设定（放正充负）
电池电流=DC低压端电流+DC高压端电流";
CM_ SG_ 2149416818 P2D_CMD2_DCDCOutputVltg_Set_50 "DCDC输出电压设定";
CM_ SG_ 2149416818 P2D_CMD2_Reserved3_50 "预留3";
CM_ SG_ 2149416818 P2D_CMD2_CommunicationState_50 "PC与DCDC通讯状态";
CM_ SG_ 2149416818 P2D_CMD2_DCDC_Fault_Clear_50 "DCDC故障清除指令";
CM_ SG_ 2149416818 P2D_CMD2_PCSOperationState_50 "PCS运行状态（预留）";
CM_ SG_ 2149416818 P2D_CMD2_DCDCLVoffControl_50 "DCDC低压下电控制";
CM_ SG_ 2149416818 P2D_CMD2_Reserved4_50 "预留4";
CM_ SG_ 2149416819 P2D_CMD2_CRC_51 "预留 （这里没必要做CRC校验吧？）";
CM_ SG_ 2149416819 P2D_CMD2_DCDCSerialNum_51 "预留（原为DCDC编号）";
CM_ SG_ 2149416819 P2D_CMD2_DCDCEnable_51 "使能DCDC命令";
CM_ SG_ 2149416819 P2D_CMD2_Reserved1_51 "预留1";
CM_ SG_ 2149416819 P2D_CMD2_DCDCWrkMdSwtch_51 "DCDC工作状态切换";
CM_ SG_ 2149416819 P2D_CMD2_DCDCWrkMdSet_51 "DCDC工作模式设定";
CM_ SG_ 2149416819 P2D_CMD2_Reserved2_51 "预留2";
CM_ SG_ 2149416819 P2D_CMD2_DCDCOutputCrrntSet_51 "电池电流设定（放正充负）
电池电流=DC低压端电流+DC高压端电流";
CM_ SG_ 2149416819 P2D_CMD2_DCDCOutputVltg_Set_51 "DCDC输出电压设定";
CM_ SG_ 2149416819 P2D_CMD2_Reserved3_51 "预留3";
CM_ SG_ 2149416819 P2D_CMD2_CommunicationState_51 "PC与DCDC通讯状态";
CM_ SG_ 2149416819 P2D_CMD2_DCDC_Fault_Clear_51 "DCDC故障清除指令";
CM_ SG_ 2149416819 P2D_CMD2_PCSOperationState_51 "PCS运行状态（预留）";
CM_ SG_ 2149416819 P2D_CMD2_DCDCLVoffControl_51 "DCDC低压下电控制";
CM_ SG_ 2149416819 P2D_CMD2_Reserved4_51 "预留4";
CM_ SG_ 2149416820 P2D_CMD2_CRC_52 "预留 （这里没必要做CRC校验吧？）";
CM_ SG_ 2149416820 P2D_CMD2_DCDCSerialNum_52 "预留（原为DCDC编号）";
CM_ SG_ 2149416820 P2D_CMD2_DCDCEnable_52 "使能DCDC命令";
CM_ SG_ 2149416820 P2D_CMD2_Reserved1_52 "预留1";
CM_ SG_ 2149416820 P2D_CMD2_DCDCWrkMdSwtch_52 "DCDC工作状态切换";
CM_ SG_ 2149416820 P2D_CMD2_DCDCWrkMdSet_52 "DCDC工作模式设定";
CM_ SG_ 2149416820 P2D_CMD2_Reserved2_52 "预留2";
CM_ SG_ 2149416820 P2D_CMD2_DCDCOutputCrrntSet_52 "电池电流设定（放正充负）
电池电流=DC低压端电流+DC高压端电流";
CM_ SG_ 2149416820 P2D_CMD2_DCDCOutputVltg_Set_52 "DCDC输出电压设定";
CM_ SG_ 2149416820 P2D_CMD2_Reserved3_52 "预留3";
CM_ SG_ 2149416820 P2D_CMD2_CommunicationState_52 "PC与DCDC通讯状态";
CM_ SG_ 2149416820 P2D_CMD2_DCDC_Fault_Clear_52 "DCDC故障清除指令";
CM_ SG_ 2149416820 P2D_CMD2_PCSOperationState_52 "PCS运行状态（预留）";
CM_ SG_ 2149416820 P2D_CMD2_DCDCLVoffControl_52 "DCDC低压下电控制";
CM_ SG_ 2149416820 P2D_CMD2_Reserved4_52 "预留4";
CM_ SG_ 2149416821 P2D_CMD2_CRC_53 "预留 （这里没必要做CRC校验吧？）";
CM_ SG_ 2149416821 P2D_CMD2_DCDCSerialNum_53 "预留（原为DCDC编号）";
CM_ SG_ 2149416821 P2D_CMD2_DCDCEnable_53 "使能DCDC命令";
CM_ SG_ 2149416821 P2D_CMD2_Reserved1_53 "预留1";
CM_ SG_ 2149416821 P2D_CMD2_DCDCWrkMdSwtch_53 "DCDC工作状态切换";
CM_ SG_ 2149416821 P2D_CMD2_DCDCWrkMdSet_53 "DCDC工作模式设定";
CM_ SG_ 2149416821 P2D_CMD2_Reserved2_53 "预留2";
CM_ SG_ 2149416821 P2D_CMD2_DCDCOutputCrrntSet_53 "电池电流设定（放正充负）
电池电流=DC低压端电流+DC高压端电流";
CM_ SG_ 2149416821 P2D_CMD2_DCDCOutputVltg_Set_53 "DCDC输出电压设定";
CM_ SG_ 2149416821 P2D_CMD2_Reserved3_53 "预留3";
CM_ SG_ 2149416821 P2D_CMD2_CommunicationState_53 "PC与DCDC通讯状态";
CM_ SG_ 2149416821 P2D_CMD2_DCDC_Fault_Clear_53 "DCDC故障清除指令";
CM_ SG_ 2149416821 P2D_CMD2_PCSOperationState_53 "PCS运行状态（预留）";
CM_ SG_ 2149416821 P2D_CMD2_DCDCLVoffControl_53 "DCDC低压下电控制";
CM_ SG_ 2149416821 P2D_CMD2_Reserved4_53 "预留4";
CM_ SG_ 2149416822 P2D_CMD2_CRC_54 "预留 （这里没必要做CRC校验吧？）";
CM_ SG_ 2149416822 P2D_CMD2_DCDCSerialNum_54 "预留（原为DCDC编号）";
CM_ SG_ 2149416822 P2D_CMD2_DCDCEnable_54 "使能DCDC命令";
CM_ SG_ 2149416822 P2D_CMD2_Reserved1_54 "预留1";
CM_ SG_ 2149416822 P2D_CMD2_DCDCWrkMdSwtch_54 "DCDC工作状态切换";
CM_ SG_ 2149416822 P2D_CMD2_DCDCWrkMdSet_54 "DCDC工作模式设定";
CM_ SG_ 2149416822 P2D_CMD2_Reserved2_54 "预留2";
CM_ SG_ 2149416822 P2D_CMD2_DCDCOutputCrrntSet_54 "电池电流设定（放正充负）
电池电流=DC低压端电流+DC高压端电流";
CM_ SG_ 2149416822 P2D_CMD2_DCDCOutputVltg_Set_54 "DCDC输出电压设定";
CM_ SG_ 2149416822 P2D_CMD2_Reserved3_54 "预留3";
CM_ SG_ 2149416822 P2D_CMD2_CommunicationState_54 "PC与DCDC通讯状态";
CM_ SG_ 2149416822 P2D_CMD2_DCDC_Fault_Clear_54 "DCDC故障清除指令";
CM_ SG_ 2149416822 P2D_CMD2_PCSOperationState_54 "PCS运行状态（预留）";
CM_ SG_ 2149416822 P2D_CMD2_DCDCLVoffControl_54 "DCDC低压下电控制";
CM_ SG_ 2149416822 P2D_CMD2_Reserved4_54 "预留4";
CM_ SG_ 2149416823 P2D_CMD2_CRC_55 "预留 （这里没必要做CRC校验吧？）";
CM_ SG_ 2149416823 P2D_CMD2_DCDCSerialNum_55 "预留（原为DCDC编号）";
CM_ SG_ 2149416823 P2D_CMD2_DCDCEnable_55 "使能DCDC命令";
CM_ SG_ 2149416823 P2D_CMD2_Reserved1_55 "预留1";
CM_ SG_ 2149416823 P2D_CMD2_DCDCWrkMdSwtch_55 "DCDC工作状态切换";
CM_ SG_ 2149416823 P2D_CMD2_DCDCWrkMdSet_55 "DCDC工作模式设定";
CM_ SG_ 2149416823 P2D_CMD2_Reserved2_55 "预留2";
CM_ SG_ 2149416823 P2D_CMD2_DCDCOutputCrrntSet_55 "电池电流设定（放正充负）
电池电流=DC低压端电流+DC高压端电流";
CM_ SG_ 2149416823 P2D_CMD2_DCDCOutputVltg_Set_55 "DCDC输出电压设定";
CM_ SG_ 2149416823 P2D_CMD2_Reserved3_55 "预留3";
CM_ SG_ 2149416823 P2D_CMD2_CommunicationState_55 "PC与DCDC通讯状态";
CM_ SG_ 2149416823 P2D_CMD2_DCDC_Fault_Clear_55 "DCDC故障清除指令";
CM_ SG_ 2149416823 P2D_CMD2_PCSOperationState_55 "PCS运行状态（预留）";
CM_ SG_ 2149416823 P2D_CMD2_DCDCLVoffControl_55 "DCDC低压下电控制";
CM_ SG_ 2149416823 P2D_CMD2_Reserved4_55 "预留4";
CM_ SG_ 2149416824 P2D_CMD2_CRC_56 "预留 （这里没必要做CRC校验吧？）";
CM_ SG_ 2149416824 P2D_CMD2_DCDCSerialNum_56 "预留（原为DCDC编号）";
CM_ SG_ 2149416824 P2D_CMD2_DCDCEnable_56 "使能DCDC命令";
CM_ SG_ 2149416824 P2D_CMD2_Reserved1_56 "预留1";
CM_ SG_ 2149416824 P2D_CMD2_DCDCWrkMdSwtch_56 "DCDC工作状态切换";
CM_ SG_ 2149416824 P2D_CMD2_DCDCWrkMdSet_56 "DCDC工作模式设定";
CM_ SG_ 2149416824 P2D_CMD2_Reserved2_56 "预留2";
CM_ SG_ 2149416824 P2D_CMD2_DCDCOutputCrrntSet_56 "电池电流设定（放正充负）
电池电流=DC低压端电流+DC高压端电流";
CM_ SG_ 2149416824 P2D_CMD2_DCDCOutputVltg_Set_56 "DCDC输出电压设定";
CM_ SG_ 2149416824 P2D_CMD2_Reserved3_56 "预留3";
CM_ SG_ 2149416824 P2D_CMD2_CommunicationState_56 "PC与DCDC通讯状态";
CM_ SG_ 2149416824 P2D_CMD2_DCDC_Fault_Clear_56 "DCDC故障清除指令";
CM_ SG_ 2149416824 P2D_CMD2_PCSOperationState_56 "PCS运行状态（预留）";
CM_ SG_ 2149416824 P2D_CMD2_DCDCLVoffControl_56 "DCDC低压下电控制";
CM_ SG_ 2149416824 P2D_CMD2_Reserved4_56 "预留4";
CM_ SG_ 2149416825 P2D_CMD2_CRC_57 "预留 （这里没必要做CRC校验吧？）";
CM_ SG_ 2149416825 P2D_CMD2_DCDCSerialNum_57 "预留（原为DCDC编号）";
CM_ SG_ 2149416825 P2D_CMD2_DCDCEnable_57 "使能DCDC命令";
CM_ SG_ 2149416825 P2D_CMD2_Reserved1_57 "预留1";
CM_ SG_ 2149416825 P2D_CMD2_DCDCWrkMdSwtch_57 "DCDC工作状态切换";
CM_ SG_ 2149416825 P2D_CMD2_DCDCWrkMdSet_57 "DCDC工作模式设定";
CM_ SG_ 2149416825 P2D_CMD2_Reserved2_57 "预留2";
CM_ SG_ 2149416825 P2D_CMD2_DCDCOutputCrrntSet_57 "电池电流设定（放正充负）
电池电流=DC低压端电流+DC高压端电流";
CM_ SG_ 2149416825 P2D_CMD2_DCDCOutputVltg_Set_57 "DCDC输出电压设定";
CM_ SG_ 2149416825 P2D_CMD2_Reserved3_57 "预留3";
CM_ SG_ 2149416825 P2D_CMD2_CommunicationState_57 "PC与DCDC通讯状态";
CM_ SG_ 2149416825 P2D_CMD2_DCDC_Fault_Clear_57 "DCDC故障清除指令";
CM_ SG_ 2149416825 P2D_CMD2_PCSOperationState_57 "PCS运行状态（预留）";
CM_ SG_ 2149416825 P2D_CMD2_DCDCLVoffControl_57 "DCDC低压下电控制";
CM_ SG_ 2149416825 P2D_CMD2_Reserved4_57 "预留4";
CM_ SG_ 2149416826 P2D_CMD2_CRC_58 "预留 （这里没必要做CRC校验吧？）";
CM_ SG_ 2149416826 P2D_CMD2_DCDCSerialNum_58 "预留（原为DCDC编号）";
CM_ SG_ 2149416826 P2D_CMD2_DCDCEnable_58 "使能DCDC命令";
CM_ SG_ 2149416826 P2D_CMD2_Reserved1_58 "预留1";
CM_ SG_ 2149416826 P2D_CMD2_DCDCWrkMdSwtch_58 "DCDC工作状态切换";
CM_ SG_ 2149416826 P2D_CMD2_DCDCWrkMdSet_58 "DCDC工作模式设定";
CM_ SG_ 2149416826 P2D_CMD2_Reserved2_58 "预留2";
CM_ SG_ 2149416826 P2D_CMD2_DCDCOutputCrrntSet_58 "电池电流设定（放正充负）
电池电流=DC低压端电流+DC高压端电流";
CM_ SG_ 2149416826 P2D_CMD2_DCDCOutputVltg_Set_58 "DCDC输出电压设定";
CM_ SG_ 2149416826 P2D_CMD2_Reserved3_58 "预留3";
CM_ SG_ 2149416826 P2D_CMD2_CommunicationState_58 "PC与DCDC通讯状态";
CM_ SG_ 2149416826 P2D_CMD2_DCDC_Fault_Clear_58 "DCDC故障清除指令";
CM_ SG_ 2149416826 P2D_CMD2_PCSOperationState_58 "PCS运行状态（预留）";
CM_ SG_ 2149416826 P2D_CMD2_DCDCLVoffControl_58 "DCDC低压下电控制";
CM_ SG_ 2149416826 P2D_CMD2_Reserved4_58 "预留4";
CM_ SG_ 2149416827 P2D_CMD2_CRC_59 "预留 （这里没必要做CRC校验吧？）";
CM_ SG_ 2149416827 P2D_CMD2_DCDCSerialNum_59 "预留（原为DCDC编号）";
CM_ SG_ 2149416827 P2D_CMD2_DCDCEnable_59 "使能DCDC命令";
CM_ SG_ 2149416827 P2D_CMD2_Reserved1_59 "预留1";
CM_ SG_ 2149416827 P2D_CMD2_DCDCWrkMdSwtch_59 "DCDC工作状态切换";
CM_ SG_ 2149416827 P2D_CMD2_DCDCWrkMdSet_59 "DCDC工作模式设定";
CM_ SG_ 2149416827 P2D_CMD2_Reserved2_59 "预留2";
CM_ SG_ 2149416827 P2D_CMD2_DCDCOutputCrrntSet_59 "电池电流设定（放正充负）
电池电流=DC低压端电流+DC高压端电流";
CM_ SG_ 2149416827 P2D_CMD2_DCDCOutputVltg_Set_59 "DCDC输出电压设定";
CM_ SG_ 2149416827 P2D_CMD2_Reserved3_59 "预留3";
CM_ SG_ 2149416827 P2D_CMD2_CommunicationState_59 "PC与DCDC通讯状态";
CM_ SG_ 2149416827 P2D_CMD2_DCDC_Fault_Clear_59 "DCDC故障清除指令";
CM_ SG_ 2149416827 P2D_CMD2_PCSOperationState_59 "PCS运行状态（预留）";
CM_ SG_ 2149416827 P2D_CMD2_DCDCLVoffControl_59 "DCDC低压下电控制";
CM_ SG_ 2149416827 P2D_CMD2_Reserved4_59 "预留4";
CM_ SG_ 2149416828 P2D_CMD2_CRC_60 "预留 （这里没必要做CRC校验吧？）";
CM_ SG_ 2149416828 P2D_CMD2_DCDCSerialNum_60 "预留（原为DCDC编号）";
CM_ SG_ 2149416828 P2D_CMD2_DCDCEnable_60 "使能DCDC命令";
CM_ SG_ 2149416828 P2D_CMD2_Reserved1_60 "预留1";
CM_ SG_ 2149416828 P2D_CMD2_DCDCWrkMdSwtch_60 "DCDC工作状态切换";
CM_ SG_ 2149416828 P2D_CMD2_DCDCWrkMdSet_60 "DCDC工作模式设定";
CM_ SG_ 2149416828 P2D_CMD2_Reserved2_60 "预留2";
CM_ SG_ 2149416828 P2D_CMD2_DCDCOutputCrrntSet_60 "电池电流设定（放正充负）
电池电流=DC低压端电流+DC高压端电流";
CM_ SG_ 2149416828 P2D_CMD2_DCDCOutputVltg_Set_60 "DCDC输出电压设定";
CM_ SG_ 2149416828 P2D_CMD2_Reserved3_60 "预留3";
CM_ SG_ 2149416828 P2D_CMD2_CommunicationState_60 "PC与DCDC通讯状态";
CM_ SG_ 2149416828 P2D_CMD2_DCDC_Fault_Clear_60 "DCDC故障清除指令";
CM_ SG_ 2149416828 P2D_CMD2_PCSOperationState_60 "PCS运行状态（预留）";
CM_ SG_ 2149416828 P2D_CMD2_DCDCLVoffControl_60 "DCDC低压下电控制";
CM_ SG_ 2149416828 P2D_CMD2_Reserved4_60 "预留4";
CM_ SG_ 2149416829 P2D_CMD2_CRC_61 "预留 （这里没必要做CRC校验吧？）";
CM_ SG_ 2149416829 P2D_CMD2_DCDCSerialNum_61 "预留（原为DCDC编号）";
CM_ SG_ 2149416829 P2D_CMD2_DCDCEnable_61 "使能DCDC命令";
CM_ SG_ 2149416829 P2D_CMD2_Reserved1_61 "预留1";
CM_ SG_ 2149416829 P2D_CMD2_DCDCWrkMdSwtch_61 "DCDC工作状态切换";
CM_ SG_ 2149416829 P2D_CMD2_DCDCWrkMdSet_61 "DCDC工作模式设定";
CM_ SG_ 2149416829 P2D_CMD2_Reserved2_61 "预留2";
CM_ SG_ 2149416829 P2D_CMD2_DCDCOutputCrrntSet_61 "电池电流设定（放正充负）
电池电流=DC低压端电流+DC高压端电流";
CM_ SG_ 2149416829 P2D_CMD2_DCDCOutputVltg_Set_61 "DCDC输出电压设定";
CM_ SG_ 2149416829 P2D_CMD2_Reserved3_61 "预留3";
CM_ SG_ 2149416829 P2D_CMD2_CommunicationState_61 "PC与DCDC通讯状态";
CM_ SG_ 2149416829 P2D_CMD2_DCDC_Fault_Clear_61 "DCDC故障清除指令";
CM_ SG_ 2149416829 P2D_CMD2_PCSOperationState_61 "PCS运行状态（预留）";
CM_ SG_ 2149416829 P2D_CMD2_DCDCLVoffControl_61 "DCDC低压下电控制";
CM_ SG_ 2149416829 P2D_CMD2_Reserved4_61 "预留4";
CM_ SG_ 2149416830 P2D_CMD2_CRC_62 "预留 （这里没必要做CRC校验吧？）";
CM_ SG_ 2149416830 P2D_CMD2_DCDCSerialNum_62 "预留（原为DCDC编号）";
CM_ SG_ 2149416830 P2D_CMD2_DCDCEnable_62 "使能DCDC命令";
CM_ SG_ 2149416830 P2D_CMD2_Reserved1_62 "预留1";
CM_ SG_ 2149416830 P2D_CMD2_DCDCWrkMdSwtch_62 "DCDC工作状态切换";
CM_ SG_ 2149416830 P2D_CMD2_DCDCWrkMdSet_62 "DCDC工作模式设定";
CM_ SG_ 2149416830 P2D_CMD2_Reserved2_62 "预留2";
CM_ SG_ 2149416830 P2D_CMD2_DCDCOutputCrrntSet_62 "电池电流设定（放正充负）
电池电流=DC低压端电流+DC高压端电流";
CM_ SG_ 2149416830 P2D_CMD2_DCDCOutputVltg_Set_62 "DCDC输出电压设定";
CM_ SG_ 2149416830 P2D_CMD2_Reserved3_62 "预留3";
CM_ SG_ 2149416830 P2D_CMD2_CommunicationState_62 "PC与DCDC通讯状态";
CM_ SG_ 2149416830 P2D_CMD2_DCDC_Fault_Clear_62 "DCDC故障清除指令";
CM_ SG_ 2149416830 P2D_CMD2_PCSOperationState_62 "PCS运行状态（预留）";
CM_ SG_ 2149416830 P2D_CMD2_DCDCLVoffControl_62 "DCDC低压下电控制";
CM_ SG_ 2149416830 P2D_CMD2_Reserved4_62 "预留4";
CM_ SG_ 2149416831 P2D_CMD2_CRC_63 "预留 （这里没必要做CRC校验吧？）";
CM_ SG_ 2149416831 P2D_CMD2_DCDCSerialNum_63 "预留（原为DCDC编号）";
CM_ SG_ 2149416831 P2D_CMD2_DCDCEnable_63 "使能DCDC命令";
CM_ SG_ 2149416831 P2D_CMD2_Reserved1_63 "预留1";
CM_ SG_ 2149416831 P2D_CMD2_DCDCWrkMdSwtch_63 "DCDC工作状态切换";
CM_ SG_ 2149416831 P2D_CMD2_DCDCWrkMdSet_63 "DCDC工作模式设定";
CM_ SG_ 2149416831 P2D_CMD2_Reserved2_63 "预留2";
CM_ SG_ 2149416831 P2D_CMD2_DCDCOutputCrrntSet_63 "电池电流设定（放正充负）
电池电流=DC低压端电流+DC高压端电流";
CM_ SG_ 2149416831 P2D_CMD2_DCDCOutputVltg_Set_63 "DCDC输出电压设定";
CM_ SG_ 2149416831 P2D_CMD2_Reserved3_63 "预留3";
CM_ SG_ 2149416831 P2D_CMD2_CommunicationState_63 "PC与DCDC通讯状态";
CM_ SG_ 2149416831 P2D_CMD2_DCDC_Fault_Clear_63 "DCDC故障清除指令";
CM_ SG_ 2149416831 P2D_CMD2_PCSOperationState_63 "PCS运行状态（预留）";
CM_ SG_ 2149416831 P2D_CMD2_DCDCLVoffControl_63 "DCDC低压下电控制";
CM_ SG_ 2149416831 P2D_CMD2_Reserved4_63 "预留4";
CM_ SG_ 2149482478 P2D_Cfg5_DCDC_Add "PC写入DCDC的地址";
CM_ SG_ 2149482478 P2D_Cfg5_Data0 "预留数据";
CM_ SG_ 2149482478 P2D_Cfg5_Data1 "预留数据";
CM_ SG_ 2149482478 P2D_Cfg5_Data2 "预留数据";
CM_ SG_ 2149482478 P2D_Cfg5_Data3 "预留数据";
CM_ SG_ 2149482478 P2D_Cfg5_Data4 "预留数据";
CM_ SG_ 2149482478 P2D_Cfg5_Data5 "预留数据";
CM_ SG_ 2149482478 P2D_Cfg5_Data6 "预留数据";
CM_ SG_ 2149547841 D2P_ALARM_EnvExtreOverTemp "环境极限过温";
CM_ SG_ 2149547841 D2P_ALARM_EnvOverTemp "环境过温";
CM_ SG_ 2149547841 D2P_ALARM_MosOverTemp "MOS管过温";
CM_ SG_ 2149547841 D2P_ALARM_MosExtreOverTemp "MOS管极限过温";
CM_ SG_ 2149547841 D2P_ALARM_HighSideOverVolt "高压侧过压故障";
CM_ SG_ 2149547841 D2P_ALARM_HighSideUnderVolt "高压侧欠压故障";
CM_ SG_ 2149547841 D2P_ALARM_LowSideOverVolt "低压侧过压故障";
CM_ SG_ 2149547841 D2P_ALARM_HighSideOverCurr "高压侧过流故障";
CM_ SG_ 2149547841 D2P_ALARM_LowSideOverCurr_HW "低压侧硬件过流故障";
CM_ SG_ 2149547841 D2P_ALARM_LowSideOverCurr_SW "低压侧软件过流故障";
CM_ SG_ 2149547841 D2P_ALARM_SecSideOverCurr_HW "谐振腔副边硬件过流";
CM_ SG_ 2149547841 D2P_ALARM_SecSideOverCurr_SW "谐振腔副边软件过流";
CM_ SG_ 2149547841 D2P_ALARM_PriSideOverCurr_HW "谐振腔源边硬件过流";
CM_ SG_ 2149547841 D2P_ALARM_PriSideOverCurr_SW "谐振腔源边软件过流";
CM_ SG_ 2149547841 D2P_ALARM_LowPowerSupplyErr "低压电源供电异常";
CM_ SG_ 2149547841 D2P_ALARM_MBMUComErr "MBMU通讯故障";
CM_ SG_ 2149547841 D2P_ALARM_DCDCMsTeSaplgErr "DCDCMOS管采样温度异常（单点）";
CM_ SG_ 2149547841 D2P_ALARM_DCDCTeSaplgErr "DCDC温度采样异常（双点及以上)";
CM_ SG_ 2149547841 D2P_ALARM_VoltSamplingErr "电压采样异常";
CM_ SG_ 2149547841 D2P_ALARM_HgSdCuSaplgErr "高压侧电流采样异常";
CM_ SG_ 2149547841 D2P_ALARM_CtrlCurrSamplingErr "控制电流采样异常";
CM_ SG_ 2149547841 D2P_ALARM_BypassFail "切旁路失败";
CM_ SG_ 2149547841 D2P_ALARM_Reserve1 "预留数据";
CM_ SG_ 2149547841 D2P_ALARM_Reserve2 "预留数据";
CM_ SG_ 2149547841 D2P_ALARM_Reserve3 "预留数据";
CM_ SG_ 2149547841 D2P_ALARM_Reserve4 "预留数据";
CM_ SG_ 2149547841 D2P_ALARM_Reserve5 "预留数据";
CM_ SG_ 2149547841 D2P_ALARM_Reserve6 "预留数据";
CM_ SG_ 2149547841 D2P_ALARM_Reserve7 "预留数据";
CM_ SG_ 2149547841 D2P_ALARM_Reserve8 "预留数据";
CM_ SG_ 2149547841 D2P_ALARM_Reserve9 "预留数据";
CM_ SG_ 2149547841 D2P_ALARM_Reserve10 "预留数据";
CM_ SG_ 2149547841 D2P_ALARM_Reserve11 "预留数据";
CM_ SG_ 2149547842 D2P_ALARM_EnvExtreOverTemp "环境极限过温";
CM_ SG_ 2149547842 D2P_ALARM_EnvOverTemp "环境过温";
CM_ SG_ 2149547842 D2P_ALARM_MosOverTemp "MOS管过温";
CM_ SG_ 2149547842 D2P_ALARM_MosExtreOverTemp "MOS管极限过温";
CM_ SG_ 2149547842 D2P_ALARM_HighSideOverVolt "高压侧过压故障";
CM_ SG_ 2149547842 D2P_ALARM_HighSideUnderVolt "高压侧欠压故障";
CM_ SG_ 2149547842 D2P_ALARM_LowSideOverVolt "低压侧过压故障";
CM_ SG_ 2149547842 D2P_ALARM_HighSideOverCurr "高压侧过流故障";
CM_ SG_ 2149547842 D2P_ALARM_LowSideOverCurr_HW "低压侧硬件过流故障";
CM_ SG_ 2149547842 D2P_ALARM_LowSideOverCurr_SW "低压侧软件过流故障";
CM_ SG_ 2149547842 D2P_ALARM_SecSideOverCurr_HW "谐振腔副边硬件过流";
CM_ SG_ 2149547842 D2P_ALARM_SecSideOverCurr_SW "谐振腔副边软件过流";
CM_ SG_ 2149547842 D2P_ALARM_PriSideOverCurr_HW "谐振腔源边硬件过流";
CM_ SG_ 2149547842 D2P_ALARM_PriSideOverCurr_SW "谐振腔源边软件过流";
CM_ SG_ 2149547842 D2P_ALARM_LowPowerSupplyErr "低压电源供电异常";
CM_ SG_ 2149547842 D2P_ALARM_MBMUComErr "MBMU通讯故障";
CM_ SG_ 2149547842 D2P_ALARM_DCDCMsTeSaplgErr "DCDCMOS管采样温度异常（单点）";
CM_ SG_ 2149547842 D2P_ALARM_DCDCTeSaplgErr "DCDC温度采样异常（双点及以上)";
CM_ SG_ 2149547842 D2P_ALARM_VoltSamplingErr "电压采样异常";
CM_ SG_ 2149547842 D2P_ALARM_HgSdCuSaplgErr "高压侧电流采样异常";
CM_ SG_ 2149547842 D2P_ALARM_CtrlCurrSamplingErr "控制电流采样异常";
CM_ SG_ 2149547842 D2P_ALARM_BypassFail "切旁路失败";
CM_ SG_ 2149547842 D2P_ALARM_Reserve1 "预留数据";
CM_ SG_ 2149547842 D2P_ALARM_Reserve2 "预留数据";
CM_ SG_ 2149547842 D2P_ALARM_Reserve3 "预留数据";
CM_ SG_ 2149547842 D2P_ALARM_Reserve4 "预留数据";
CM_ SG_ 2149547842 D2P_ALARM_Reserve5 "预留数据";
CM_ SG_ 2149547842 D2P_ALARM_Reserve6 "预留数据";
CM_ SG_ 2149547842 D2P_ALARM_Reserve7 "预留数据";
CM_ SG_ 2149547842 D2P_ALARM_Reserve8 "预留数据";
CM_ SG_ 2149547842 D2P_ALARM_Reserve9 "预留数据";
CM_ SG_ 2149547842 D2P_ALARM_Reserve10 "预留数据";
CM_ SG_ 2149547842 D2P_ALARM_Reserve11 "预留数据";
CM_ SG_ 2149547843 D2P_ALARM_EnvExtreOverTemp "环境极限过温";
CM_ SG_ 2149547843 D2P_ALARM_EnvOverTemp "环境过温";
CM_ SG_ 2149547843 D2P_ALARM_MosOverTemp "MOS管过温";
CM_ SG_ 2149547843 D2P_ALARM_MosExtreOverTemp "MOS管极限过温";
CM_ SG_ 2149547843 D2P_ALARM_HighSideOverVolt "高压侧过压故障";
CM_ SG_ 2149547843 D2P_ALARM_HighSideUnderVolt "高压侧欠压故障";
CM_ SG_ 2149547843 D2P_ALARM_LowSideOverVolt "低压侧过压故障";
CM_ SG_ 2149547843 D2P_ALARM_HighSideOverCurr "高压侧过流故障";
CM_ SG_ 2149547843 D2P_ALARM_LowSideOverCurr_HW "低压侧硬件过流故障";
CM_ SG_ 2149547843 D2P_ALARM_LowSideOverCurr_SW "低压侧软件过流故障";
CM_ SG_ 2149547843 D2P_ALARM_SecSideOverCurr_HW "谐振腔副边硬件过流";
CM_ SG_ 2149547843 D2P_ALARM_SecSideOverCurr_SW "谐振腔副边软件过流";
CM_ SG_ 2149547843 D2P_ALARM_PriSideOverCurr_HW "谐振腔源边硬件过流";
CM_ SG_ 2149547843 D2P_ALARM_PriSideOverCurr_SW "谐振腔源边软件过流";
CM_ SG_ 2149547843 D2P_ALARM_LowPowerSupplyErr "低压电源供电异常";
CM_ SG_ 2149547843 D2P_ALARM_MBMUComErr "MBMU通讯故障";
CM_ SG_ 2149547843 D2P_ALARM_DCDCMsTeSaplgErr "DCDCMOS管采样温度异常（单点）";
CM_ SG_ 2149547843 D2P_ALARM_DCDCTeSaplgErr "DCDC温度采样异常（双点及以上)";
CM_ SG_ 2149547843 D2P_ALARM_VoltSamplingErr "电压采样异常";
CM_ SG_ 2149547843 D2P_ALARM_HgSdCuSaplgErr "高压侧电流采样异常";
CM_ SG_ 2149547843 D2P_ALARM_CtrlCurrSamplingErr "控制电流采样异常";
CM_ SG_ 2149547843 D2P_ALARM_BypassFail "切旁路失败";
CM_ SG_ 2149547843 D2P_ALARM_Reserve1 "预留数据";
CM_ SG_ 2149547843 D2P_ALARM_Reserve2 "预留数据";
CM_ SG_ 2149547843 D2P_ALARM_Reserve3 "预留数据";
CM_ SG_ 2149547843 D2P_ALARM_Reserve4 "预留数据";
CM_ SG_ 2149547843 D2P_ALARM_Reserve5 "预留数据";
CM_ SG_ 2149547843 D2P_ALARM_Reserve6 "预留数据";
CM_ SG_ 2149547843 D2P_ALARM_Reserve7 "预留数据";
CM_ SG_ 2149547843 D2P_ALARM_Reserve8 "预留数据";
CM_ SG_ 2149547843 D2P_ALARM_Reserve9 "预留数据";
CM_ SG_ 2149547843 D2P_ALARM_Reserve10 "预留数据";
CM_ SG_ 2149547843 D2P_ALARM_Reserve11 "预留数据";
CM_ SG_ 2149547844 D2P_ALARM_EnvExtreOverTemp "环境极限过温";
CM_ SG_ 2149547844 D2P_ALARM_EnvOverTemp "环境过温";
CM_ SG_ 2149547844 D2P_ALARM_MosOverTemp "MOS管过温";
CM_ SG_ 2149547844 D2P_ALARM_MosExtreOverTemp "MOS管极限过温";
CM_ SG_ 2149547844 D2P_ALARM_HighSideOverVolt "高压侧过压故障";
CM_ SG_ 2149547844 D2P_ALARM_HighSideUnderVolt "高压侧欠压故障";
CM_ SG_ 2149547844 D2P_ALARM_LowSideOverVolt "低压侧过压故障";
CM_ SG_ 2149547844 D2P_ALARM_HighSideOverCurr "高压侧过流故障";
CM_ SG_ 2149547844 D2P_ALARM_LowSideOverCurr_HW "低压侧硬件过流故障";
CM_ SG_ 2149547844 D2P_ALARM_LowSideOverCurr_SW "低压侧软件过流故障";
CM_ SG_ 2149547844 D2P_ALARM_SecSideOverCurr_HW "谐振腔副边硬件过流";
CM_ SG_ 2149547844 D2P_ALARM_SecSideOverCurr_SW "谐振腔副边软件过流";
CM_ SG_ 2149547844 D2P_ALARM_PriSideOverCurr_HW "谐振腔源边硬件过流";
CM_ SG_ 2149547844 D2P_ALARM_PriSideOverCurr_SW "谐振腔源边软件过流";
CM_ SG_ 2149547844 D2P_ALARM_LowPowerSupplyErr "低压电源供电异常";
CM_ SG_ 2149547844 D2P_ALARM_MBMUComErr "MBMU通讯故障";
CM_ SG_ 2149547844 D2P_ALARM_DCDCMsTeSaplgErr "DCDCMOS管采样温度异常（单点）";
CM_ SG_ 2149547844 D2P_ALARM_DCDCTeSaplgErr "DCDC温度采样异常（双点及以上)";
CM_ SG_ 2149547844 D2P_ALARM_VoltSamplingErr "电压采样异常";
CM_ SG_ 2149547844 D2P_ALARM_HgSdCuSaplgErr "高压侧电流采样异常";
CM_ SG_ 2149547844 D2P_ALARM_CtrlCurrSamplingErr "控制电流采样异常";
CM_ SG_ 2149547844 D2P_ALARM_BypassFail "切旁路失败";
CM_ SG_ 2149547844 D2P_ALARM_Reserve1 "预留数据";
CM_ SG_ 2149547844 D2P_ALARM_Reserve2 "预留数据";
CM_ SG_ 2149547844 D2P_ALARM_Reserve3 "预留数据";
CM_ SG_ 2149547844 D2P_ALARM_Reserve4 "预留数据";
CM_ SG_ 2149547844 D2P_ALARM_Reserve5 "预留数据";
CM_ SG_ 2149547844 D2P_ALARM_Reserve6 "预留数据";
CM_ SG_ 2149547844 D2P_ALARM_Reserve7 "预留数据";
CM_ SG_ 2149547844 D2P_ALARM_Reserve8 "预留数据";
CM_ SG_ 2149547844 D2P_ALARM_Reserve9 "预留数据";
CM_ SG_ 2149547844 D2P_ALARM_Reserve10 "预留数据";
CM_ SG_ 2149547844 D2P_ALARM_Reserve11 "预留数据";
CM_ SG_ 2149547845 D2P_ALARM_EnvExtreOverTemp "环境极限过温";
CM_ SG_ 2149547845 D2P_ALARM_EnvOverTemp "环境过温";
CM_ SG_ 2149547845 D2P_ALARM_MosOverTemp "MOS管过温";
CM_ SG_ 2149547845 D2P_ALARM_MosExtreOverTemp "MOS管极限过温";
CM_ SG_ 2149547845 D2P_ALARM_HighSideOverVolt "高压侧过压故障";
CM_ SG_ 2149547845 D2P_ALARM_HighSideUnderVolt "高压侧欠压故障";
CM_ SG_ 2149547845 D2P_ALARM_LowSideOverVolt "低压侧过压故障";
CM_ SG_ 2149547845 D2P_ALARM_HighSideOverCurr "高压侧过流故障";
CM_ SG_ 2149547845 D2P_ALARM_LowSideOverCurr_HW "低压侧硬件过流故障";
CM_ SG_ 2149547845 D2P_ALARM_LowSideOverCurr_SW "低压侧软件过流故障";
CM_ SG_ 2149547845 D2P_ALARM_SecSideOverCurr_HW "谐振腔副边硬件过流";
CM_ SG_ 2149547845 D2P_ALARM_SecSideOverCurr_SW "谐振腔副边软件过流";
CM_ SG_ 2149547845 D2P_ALARM_PriSideOverCurr_HW "谐振腔源边硬件过流";
CM_ SG_ 2149547845 D2P_ALARM_PriSideOverCurr_SW "谐振腔源边软件过流";
CM_ SG_ 2149547845 D2P_ALARM_LowPowerSupplyErr "低压电源供电异常";
CM_ SG_ 2149547845 D2P_ALARM_MBMUComErr "MBMU通讯故障";
CM_ SG_ 2149547845 D2P_ALARM_DCDCMsTeSaplgErr "DCDCMOS管采样温度异常（单点）";
CM_ SG_ 2149547845 D2P_ALARM_DCDCTeSaplgErr "DCDC温度采样异常（双点及以上)";
CM_ SG_ 2149547845 D2P_ALARM_VoltSamplingErr "电压采样异常";
CM_ SG_ 2149547845 D2P_ALARM_HgSdCuSaplgErr "高压侧电流采样异常";
CM_ SG_ 2149547845 D2P_ALARM_CtrlCurrSamplingErr "控制电流采样异常";
CM_ SG_ 2149547845 D2P_ALARM_BypassFail "切旁路失败";
CM_ SG_ 2149547845 D2P_ALARM_Reserve1 "预留数据";
CM_ SG_ 2149547845 D2P_ALARM_Reserve2 "预留数据";
CM_ SG_ 2149547845 D2P_ALARM_Reserve3 "预留数据";
CM_ SG_ 2149547845 D2P_ALARM_Reserve4 "预留数据";
CM_ SG_ 2149547845 D2P_ALARM_Reserve5 "预留数据";
CM_ SG_ 2149547845 D2P_ALARM_Reserve6 "预留数据";
CM_ SG_ 2149547845 D2P_ALARM_Reserve7 "预留数据";
CM_ SG_ 2149547845 D2P_ALARM_Reserve8 "预留数据";
CM_ SG_ 2149547845 D2P_ALARM_Reserve9 "预留数据";
CM_ SG_ 2149547845 D2P_ALARM_Reserve10 "预留数据";
CM_ SG_ 2149547845 D2P_ALARM_Reserve11 "预留数据";
CM_ SG_ 2149547846 D2P_ALARM_EnvExtreOverTemp "环境极限过温";
CM_ SG_ 2149547846 D2P_ALARM_EnvOverTemp "环境过温";
CM_ SG_ 2149547846 D2P_ALARM_MosOverTemp "MOS管过温";
CM_ SG_ 2149547846 D2P_ALARM_MosExtreOverTemp "MOS管极限过温";
CM_ SG_ 2149547846 D2P_ALARM_HighSideOverVolt "高压侧过压故障";
CM_ SG_ 2149547846 D2P_ALARM_HighSideUnderVolt "高压侧欠压故障";
CM_ SG_ 2149547846 D2P_ALARM_LowSideOverVolt "低压侧过压故障";
CM_ SG_ 2149547846 D2P_ALARM_HighSideOverCurr "高压侧过流故障";
CM_ SG_ 2149547846 D2P_ALARM_LowSideOverCurr_HW "低压侧硬件过流故障";
CM_ SG_ 2149547846 D2P_ALARM_LowSideOverCurr_SW "低压侧软件过流故障";
CM_ SG_ 2149547846 D2P_ALARM_SecSideOverCurr_HW "谐振腔副边硬件过流";
CM_ SG_ 2149547846 D2P_ALARM_SecSideOverCurr_SW "谐振腔副边软件过流";
CM_ SG_ 2149547846 D2P_ALARM_PriSideOverCurr_HW "谐振腔源边硬件过流";
CM_ SG_ 2149547846 D2P_ALARM_PriSideOverCurr_SW "谐振腔源边软件过流";
CM_ SG_ 2149547846 D2P_ALARM_LowPowerSupplyErr "低压电源供电异常";
CM_ SG_ 2149547846 D2P_ALARM_MBMUComErr "MBMU通讯故障";
CM_ SG_ 2149547846 D2P_ALARM_DCDCMsTeSaplgErr "DCDCMOS管采样温度异常（单点）";
CM_ SG_ 2149547846 D2P_ALARM_DCDCTeSaplgErr "DCDC温度采样异常（双点及以上)";
CM_ SG_ 2149547846 D2P_ALARM_VoltSamplingErr "电压采样异常";
CM_ SG_ 2149547846 D2P_ALARM_HgSdCuSaplgErr "高压侧电流采样异常";
CM_ SG_ 2149547846 D2P_ALARM_CtrlCurrSamplingErr "控制电流采样异常";
CM_ SG_ 2149547846 D2P_ALARM_BypassFail "切旁路失败";
CM_ SG_ 2149547846 D2P_ALARM_Reserve1 "预留数据";
CM_ SG_ 2149547846 D2P_ALARM_Reserve2 "预留数据";
CM_ SG_ 2149547846 D2P_ALARM_Reserve3 "预留数据";
CM_ SG_ 2149547846 D2P_ALARM_Reserve4 "预留数据";
CM_ SG_ 2149547846 D2P_ALARM_Reserve5 "预留数据";
CM_ SG_ 2149547846 D2P_ALARM_Reserve6 "预留数据";
CM_ SG_ 2149547846 D2P_ALARM_Reserve7 "预留数据";
CM_ SG_ 2149547846 D2P_ALARM_Reserve8 "预留数据";
CM_ SG_ 2149547846 D2P_ALARM_Reserve9 "预留数据";
CM_ SG_ 2149547846 D2P_ALARM_Reserve10 "预留数据";
CM_ SG_ 2149547846 D2P_ALARM_Reserve11 "预留数据";
CM_ SG_ 2149547847 D2P_ALARM_EnvExtreOverTemp "环境极限过温";
CM_ SG_ 2149547847 D2P_ALARM_EnvOverTemp "环境过温";
CM_ SG_ 2149547847 D2P_ALARM_MosOverTemp "MOS管过温";
CM_ SG_ 2149547847 D2P_ALARM_MosExtreOverTemp "MOS管极限过温";
CM_ SG_ 2149547847 D2P_ALARM_HighSideOverVolt "高压侧过压故障";
CM_ SG_ 2149547847 D2P_ALARM_HighSideUnderVolt "高压侧欠压故障";
CM_ SG_ 2149547847 D2P_ALARM_LowSideOverVolt "低压侧过压故障";
CM_ SG_ 2149547847 D2P_ALARM_HighSideOverCurr "高压侧过流故障";
CM_ SG_ 2149547847 D2P_ALARM_LowSideOverCurr_HW "低压侧硬件过流故障";
CM_ SG_ 2149547847 D2P_ALARM_LowSideOverCurr_SW "低压侧软件过流故障";
CM_ SG_ 2149547847 D2P_ALARM_SecSideOverCurr_HW "谐振腔副边硬件过流";
CM_ SG_ 2149547847 D2P_ALARM_SecSideOverCurr_SW "谐振腔副边软件过流";
CM_ SG_ 2149547847 D2P_ALARM_PriSideOverCurr_HW "谐振腔源边硬件过流";
CM_ SG_ 2149547847 D2P_ALARM_PriSideOverCurr_SW "谐振腔源边软件过流";
CM_ SG_ 2149547847 D2P_ALARM_LowPowerSupplyErr "低压电源供电异常";
CM_ SG_ 2149547847 D2P_ALARM_MBMUComErr "MBMU通讯故障";
CM_ SG_ 2149547847 D2P_ALARM_DCDCMsTeSaplgErr "DCDCMOS管采样温度异常（单点）";
CM_ SG_ 2149547847 D2P_ALARM_DCDCTeSaplgErr "DCDC温度采样异常（双点及以上)";
CM_ SG_ 2149547847 D2P_ALARM_VoltSamplingErr "电压采样异常";
CM_ SG_ 2149547847 D2P_ALARM_HgSdCuSaplgErr "高压侧电流采样异常";
CM_ SG_ 2149547847 D2P_ALARM_CtrlCurrSamplingErr "控制电流采样异常";
CM_ SG_ 2149547847 D2P_ALARM_BypassFail "切旁路失败";
CM_ SG_ 2149547847 D2P_ALARM_Reserve1 "预留数据";
CM_ SG_ 2149547847 D2P_ALARM_Reserve2 "预留数据";
CM_ SG_ 2149547847 D2P_ALARM_Reserve3 "预留数据";
CM_ SG_ 2149547847 D2P_ALARM_Reserve4 "预留数据";
CM_ SG_ 2149547847 D2P_ALARM_Reserve5 "预留数据";
CM_ SG_ 2149547847 D2P_ALARM_Reserve6 "预留数据";
CM_ SG_ 2149547847 D2P_ALARM_Reserve7 "预留数据";
CM_ SG_ 2149547847 D2P_ALARM_Reserve8 "预留数据";
CM_ SG_ 2149547847 D2P_ALARM_Reserve9 "预留数据";
CM_ SG_ 2149547847 D2P_ALARM_Reserve10 "预留数据";
CM_ SG_ 2149547847 D2P_ALARM_Reserve11 "预留数据";
VAL_ 2149416775 P2D_CMD2_DCDCEnable_07 0 "Disable" 1 "Enable" ;
VAL_ 2149416775 P2D_CMD2_DCDCWrkMdSwtch_07 0 "Standby" 1 "Normal Run" 2 "Bypass" 3 "Reserved" ;
VAL_ 2149416775 P2D_CMD2_DCDCWrkMdSet_07 0 "Constant Vlotage" 1 "Constant Current" 2 "Steady Current(not greater than)" 3 "Steady Current(not less than)" ;
VAL_ 2149416775 P2D_CMD2_CommunicationState_07 0 "Normal" 1 "CAN lost" ;
VAL_ 2149416775 P2D_CMD2_DCDC_Fault_Clear_07 0 "Not Clear" 1 "Clear" ;
VAL_ 2149416775 P2D_CMD2_PCSOperationState_07 0 "Standby" 1 "Discharge" 2 "Charge" 3 "Fault" ;
VAL_ 2149416775 P2D_CMD2_DCDCLVoffControl_07 0 "不允许低压下电" 1 "允许低压下电" ;
VAL_ 2149416776 P2D_CMD2_DCDCEnable_08 0 "Disable" 1 "Enable" ;
VAL_ 2149416776 P2D_CMD2_DCDCWrkMdSwtch_08 0 "Standby" 1 "Normal Run" 2 "Bypass" 3 "Reserved" ;
VAL_ 2149416776 P2D_CMD2_DCDCWrkMdSet_08 0 "Constant Vlotage" 1 "Constant Current" 2 "Steady Current(not greater than)" 3 "Steady Current(not less than)" ;
VAL_ 2149416776 P2D_CMD2_CommunicationState_08 0 "Normal" 1 "CAN lost" ;
VAL_ 2149416776 P2D_CMD2_DCDC_Fault_Clear_08 0 "Not Clear" 1 "Clear" ;
VAL_ 2149416776 P2D_CMD2_PCSOperationState_08 0 "Standby" 1 "Discharge" 2 "Charge" 3 "Fault" ;
VAL_ 2149416776 P2D_CMD2_DCDCLVoffControl_08 0 "不允许低压下电" 1 "允许低压下电" ;
VAL_ 2149416777 P2D_CMD2_DCDCEnable_09 0 "Disable" 1 "Enable" ;
VAL_ 2149416777 P2D_CMD2_DCDCWrkMdSwtch_09 0 "Standby" 1 "Normal Run" 2 "Bypass" 3 "Reserved" ;
VAL_ 2149416777 P2D_CMD2_DCDCWrkMdSet_09 0 "Constant Vlotage" 1 "Constant Current" 2 "Steady Current(not greater than)" 3 "Steady Current(not less than)" ;
VAL_ 2149416777 P2D_CMD2_CommunicationState_09 0 "Normal" 1 "CAN lost" ;
VAL_ 2149416777 P2D_CMD2_DCDC_Fault_Clear_09 0 "Not Clear" 1 "Clear" ;
VAL_ 2149416777 P2D_CMD2_PCSOperationState_09 0 "Standby" 1 "Discharge" 2 "Charge" 3 "Fault" ;
VAL_ 2149416777 P2D_CMD2_DCDCLVoffControl_09 0 "不允许低压下电" 1 "允许低压下电" ;
VAL_ 2149416778 P2D_CMD2_DCDCEnable_10 0 "Disable" 1 "Enable" ;
VAL_ 2149416778 P2D_CMD2_DCDCWrkMdSwtch_10 0 "Standby" 1 "Normal Run" 2 "Bypass" 3 "Reserved" ;
VAL_ 2149416778 P2D_CMD2_DCDCWrkMdSet_10 0 "Constant Vlotage" 1 "Constant Current" 2 "Steady Current(not greater than)" 3 "Steady Current(not less than)" ;
VAL_ 2149416778 P2D_CMD2_CommunicationState_10 0 "Normal" 1 "CAN lost" ;
VAL_ 2149416778 P2D_CMD2_DCDC_Fault_Clear_10 0 "Not Clear" 1 "Clear" ;
VAL_ 2149416778 P2D_CMD2_PCSOperationState_10 0 "Standby" 1 "Discharge" 2 "Charge" 3 "Fault" ;
VAL_ 2149416778 P2D_CMD2_DCDCLVoffControl_10 0 "不允许低压下电" 1 "允许低压下电" ;
VAL_ 2149416779 P2D_CMD2_DCDCEnable_11 0 "Disable" 1 "Enable" ;
VAL_ 2149416779 P2D_CMD2_DCDCWrkMdSwtch_11 0 "Standby" 1 "Normal Run" 2 "Bypass" 3 "Reserved" ;
VAL_ 2149416779 P2D_CMD2_DCDCWrkMdSet_11 0 "Constant Vlotage" 1 "Constant Current" 2 "Steady Current(not greater than)" 3 "Steady Current(not less than)" ;
VAL_ 2149416779 P2D_CMD2_CommunicationState_11 0 "Normal" 1 "CAN lost" ;
VAL_ 2149416779 P2D_CMD2_DCDC_Fault_Clear_11 0 "Not Clear" 1 "Clear" ;
VAL_ 2149416779 P2D_CMD2_PCSOperationState_11 0 "Standby" 1 "Discharge" 2 "Charge" 3 "Fault" ;
VAL_ 2149416779 P2D_CMD2_DCDCLVoffControl_11 0 "不允许低压下电" 1 "允许低压下电" ;
VAL_ 2149416780 P2D_CMD2_DCDCEnable_12 0 "Disable" 1 "Enable" ;
VAL_ 2149416780 P2D_CMD2_DCDCWrkMdSwtch_12 0 "Standby" 1 "Normal Run" 2 "Bypass" 3 "Reserved" ;
VAL_ 2149416780 P2D_CMD2_DCDCWrkMdSet_12 0 "Constant Vlotage" 1 "Constant Current" 2 "Steady Current(not greater than)" 3 "Steady Current(not less than)" ;
VAL_ 2149416780 P2D_CMD2_CommunicationState_12 0 "Normal" 1 "CAN lost" ;
VAL_ 2149416780 P2D_CMD2_DCDC_Fault_Clear_12 0 "Not Clear" 1 "Clear" ;
VAL_ 2149416780 P2D_CMD2_PCSOperationState_12 0 "Standby" 1 "Discharge" 2 "Charge" 3 "Fault" ;
VAL_ 2149416780 P2D_CMD2_DCDCLVoffControl_12 0 "不允许低压下电" 1 "允许低压下电" ;
VAL_ 2149416781 P2D_CMD2_DCDCEnable_13 0 "Disable" 1 "Enable" ;
VAL_ 2149416781 P2D_CMD2_DCDCWrkMdSwtch_13 0 "Standby" 1 "Normal Run" 2 "Bypass" 3 "Reserved" ;
VAL_ 2149416781 P2D_CMD2_DCDCWrkMdSet_13 0 "Constant Vlotage" 1 "Constant Current" 2 "Steady Current(not greater than)" 3 "Steady Current(not less than)" ;
VAL_ 2149416781 P2D_CMD2_CommunicationState_13 0 "Normal" 1 "CAN lost" ;
VAL_ 2149416781 P2D_CMD2_DCDC_Fault_Clear_13 0 "Not Clear" 1 "Clear" ;
VAL_ 2149416781 P2D_CMD2_PCSOperationState_13 0 "Standby" 1 "Discharge" 2 "Charge" 3 "Fault" ;
VAL_ 2149416781 P2D_CMD2_DCDCLVoffControl_13 0 "不允许低压下电" 1 "允许低压下电" ;
VAL_ 2149416782 P2D_CMD2_DCDCEnable_14 0 "Disable" 1 "Enable" ;
VAL_ 2149416782 P2D_CMD2_DCDCWrkMdSwtch_14 0 "Standby" 1 "Normal Run" 2 "Bypass" 3 "Reserved" ;
VAL_ 2149416782 P2D_CMD2_DCDCWrkMdSet_14 0 "Constant Vlotage" 1 "Constant Current" 2 "Steady Current(not greater than)" 3 "Steady Current(not less than)" ;
VAL_ 2149416782 P2D_CMD2_CommunicationState_14 0 "Normal" 1 "CAN lost" ;
VAL_ 2149416782 P2D_CMD2_DCDC_Fault_Clear_14 0 "Not Clear" 1 "Clear" ;
VAL_ 2149416782 P2D_CMD2_PCSOperationState_14 0 "Standby" 1 "Discharge" 2 "Charge" 3 "Fault" ;
VAL_ 2149416782 P2D_CMD2_DCDCLVoffControl_14 0 "不允许低压下电" 1 "允许低压下电" ;
VAL_ 2149416783 P2D_CMD2_DCDCEnable_15 0 "Disable" 1 "Enable" ;
VAL_ 2149416783 P2D_CMD2_DCDCWrkMdSwtch_15 0 "Standby" 1 "Normal Run" 2 "Bypass" 3 "Reserved" ;
VAL_ 2149416783 P2D_CMD2_DCDCWrkMdSet_15 0 "Constant Vlotage" 1 "Constant Current" 2 "Steady Current(not greater than)" 3 "Steady Current(not less than)" ;
VAL_ 2149416783 P2D_CMD2_CommunicationState_15 0 "Normal" 1 "CAN lost" ;
VAL_ 2149416783 P2D_CMD2_DCDC_Fault_Clear_15 0 "Not Clear" 1 "Clear" ;
VAL_ 2149416783 P2D_CMD2_PCSOperationState_15 0 "Standby" 1 "Discharge" 2 "Charge" 3 "Fault" ;
VAL_ 2149416783 P2D_CMD2_DCDCLVoffControl_15 0 "不允许低压下电" 1 "允许低压下电" ;
VAL_ 2149416784 P2D_CMD2_DCDCEnable_16 0 "Disable" 1 "Enable" ;
VAL_ 2149416784 P2D_CMD2_DCDCWrkMdSwtch_16 0 "Standby" 1 "Normal Run" 2 "Bypass" 3 "Reserved" ;
VAL_ 2149416784 P2D_CMD2_DCDCWrkMdSet_16 0 "Constant Vlotage" 1 "Constant Current" 2 "Steady Current(not greater than)" 3 "Steady Current(not less than)" ;
VAL_ 2149416784 P2D_CMD2_CommunicationState_16 0 "Normal" 1 "CAN lost" ;
VAL_ 2149416784 P2D_CMD2_DCDC_Fault_Clear_16 0 "Not Clear" 1 "Clear" ;
VAL_ 2149416784 P2D_CMD2_PCSOperationState_16 0 "Standby" 1 "Discharge" 2 "Charge" 3 "Fault" ;
VAL_ 2149416784 P2D_CMD2_DCDCLVoffControl_16 0 "不允许低压下电" 1 "允许低压下电" ;
VAL_ 2149416785 P2D_CMD2_DCDCEnable_17 0 "Disable" 1 "Enable" ;
VAL_ 2149416785 P2D_CMD2_DCDCWrkMdSwtch_17 0 "Standby" 1 "Normal Run" 2 "Bypass" 3 "Reserved" ;
VAL_ 2149416785 P2D_CMD2_DCDCWrkMdSet_17 0 "Constant Vlotage" 1 "Constant Current" 2 "Steady Current(not greater than)" 3 "Steady Current(not less than)" ;
VAL_ 2149416785 P2D_CMD2_CommunicationState_17 0 "Normal" 1 "CAN lost" ;
VAL_ 2149416785 P2D_CMD2_DCDC_Fault_Clear_17 0 "Not Clear" 1 "Clear" ;
VAL_ 2149416785 P2D_CMD2_PCSOperationState_17 0 "Standby" 1 "Discharge" 2 "Charge" 3 "Fault" ;
VAL_ 2149416785 P2D_CMD2_DCDCLVoffControl_17 0 "不允许低压下电" 1 "允许低压下电" ;
VAL_ 2149416786 P2D_CMD2_DCDCEnable_18 0 "Disable" 1 "Enable" ;
VAL_ 2149416786 P2D_CMD2_DCDCWrkMdSwtch_18 0 "Standby" 1 "Normal Run" 2 "Bypass" 3 "Reserved" ;
VAL_ 2149416786 P2D_CMD2_DCDCWrkMdSet_18 0 "Constant Vlotage" 1 "Constant Current" 2 "Steady Current(not greater than)" 3 "Steady Current(not less than)" ;
VAL_ 2149416786 P2D_CMD2_CommunicationState_18 0 "Normal" 1 "CAN lost" ;
VAL_ 2149416786 P2D_CMD2_DCDC_Fault_Clear_18 0 "Not Clear" 1 "Clear" ;
VAL_ 2149416786 P2D_CMD2_PCSOperationState_18 0 "Standby" 1 "Discharge" 2 "Charge" 3 "Fault" ;
VAL_ 2149416786 P2D_CMD2_DCDCLVoffControl_18 0 "不允许低压下电" 1 "允许低压下电" ;
VAL_ 2149416787 P2D_CMD2_DCDCEnable_19 0 "Disable" 1 "Enable" ;
VAL_ 2149416787 P2D_CMD2_DCDCWrkMdSwtch_19 0 "Standby" 1 "Normal Run" 2 "Bypass" 3 "Reserved" ;
VAL_ 2149416787 P2D_CMD2_DCDCWrkMdSet_19 0 "Constant Vlotage" 1 "Constant Current" 2 "Steady Current(not greater than)" 3 "Steady Current(not less than)" ;
VAL_ 2149416787 P2D_CMD2_CommunicationState_19 0 "Normal" 1 "CAN lost" ;
VAL_ 2149416787 P2D_CMD2_DCDC_Fault_Clear_19 0 "Not Clear" 1 "Clear" ;
VAL_ 2149416787 P2D_CMD2_PCSOperationState_19 0 "Standby" 1 "Discharge" 2 "Charge" 3 "Fault" ;
VAL_ 2149416787 P2D_CMD2_DCDCLVoffControl_19 0 "不允许低压下电" 1 "允许低压下电" ;
VAL_ 2149416788 P2D_CMD2_DCDCEnable_20 0 "Disable" 1 "Enable" ;
VAL_ 2149416788 P2D_CMD2_DCDCWrkMdSwtch_20 0 "Standby" 1 "Normal Run" 2 "Bypass" 3 "Reserved" ;
VAL_ 2149416788 P2D_CMD2_DCDCWrkMdSet_20 0 "Constant Vlotage" 1 "Constant Current" 2 "Steady Current(not greater than)" 3 "Steady Current(not less than)" ;
VAL_ 2149416788 P2D_CMD2_CommunicationState_20 0 "Normal" 1 "CAN lost" ;
VAL_ 2149416788 P2D_CMD2_DCDC_Fault_Clear_20 0 "Not Clear" 1 "Clear" ;
VAL_ 2149416788 P2D_CMD2_PCSOperationState_20 0 "Standby" 1 "Discharge" 2 "Charge" 3 "Fault" ;
VAL_ 2149416788 P2D_CMD2_DCDCLVoffControl_20 0 "不允许低压下电" 1 "允许低压下电" ;
VAL_ 2149416789 P2D_CMD2_DCDCEnable_21 0 "Disable" 1 "Enable" ;
VAL_ 2149416789 P2D_CMD2_DCDCWrkMdSwtch_21 0 "Standby" 1 "Normal Run" 2 "Bypass" 3 "Reserved" ;
VAL_ 2149416789 P2D_CMD2_DCDCWrkMdSet_21 0 "Constant Vlotage" 1 "Constant Current" 2 "Steady Current(not greater than)" 3 "Steady Current(not less than)" ;
VAL_ 2149416789 P2D_CMD2_CommunicationState_21 0 "Normal" 1 "CAN lost" ;
VAL_ 2149416789 P2D_CMD2_DCDC_Fault_Clear_21 0 "Not Clear" 1 "Clear" ;
VAL_ 2149416789 P2D_CMD2_PCSOperationState_21 0 "Standby" 1 "Discharge" 2 "Charge" 3 "Fault" ;
VAL_ 2149416789 P2D_CMD2_DCDCLVoffControl_21 0 "不允许低压下电" 1 "允许低压下电" ;
VAL_ 2149416790 P2D_CMD2_DCDCEnable_22 0 "Disable" 1 "Enable" ;
VAL_ 2149416790 P2D_CMD2_DCDCWrkMdSwtch_22 0 "Standby" 1 "Normal Run" 2 "Bypass" 3 "Reserved" ;
VAL_ 2149416790 P2D_CMD2_DCDCWrkMdSet_22 0 "Constant Vlotage" 1 "Constant Current" 2 "Steady Current(not greater than)" 3 "Steady Current(not less than)" ;
VAL_ 2149416790 P2D_CMD2_CommunicationState_22 0 "Normal" 1 "CAN lost" ;
VAL_ 2149416790 P2D_CMD2_DCDC_Fault_Clear_22 0 "Not Clear" 1 "Clear" ;
VAL_ 2149416790 P2D_CMD2_PCSOperationState_22 0 "Standby" 1 "Discharge" 2 "Charge" 3 "Fault" ;
VAL_ 2149416790 P2D_CMD2_DCDCLVoffControl_22 0 "不允许低压下电" 1 "允许低压下电" ;
VAL_ 2149416791 P2D_CMD2_DCDCEnable_23 0 "Disable" 1 "Enable" ;
VAL_ 2149416791 P2D_CMD2_DCDCWrkMdSwtch_23 0 "Standby" 1 "Normal Run" 2 "Bypass" 3 "Reserved" ;
VAL_ 2149416791 P2D_CMD2_DCDCWrkMdSet_23 0 "Constant Vlotage" 1 "Constant Current" 2 "Steady Current(not greater than)" 3 "Steady Current(not less than)" ;
VAL_ 2149416791 P2D_CMD2_CommunicationState_23 0 "Normal" 1 "CAN lost" ;
VAL_ 2149416791 P2D_CMD2_DCDC_Fault_Clear_23 0 "Not Clear" 1 "Clear" ;
VAL_ 2149416791 P2D_CMD2_PCSOperationState_23 0 "Standby" 1 "Discharge" 2 "Charge" 3 "Fault" ;
VAL_ 2149416791 P2D_CMD2_DCDCLVoffControl_23 0 "不允许低压下电" 1 "允许低压下电" ;
VAL_ 2149416792 P2D_CMD2_DCDCEnable_24 0 "Disable" 1 "Enable" ;
VAL_ 2149416792 P2D_CMD2_DCDCWrkMdSwtch_24 0 "Standby" 1 "Normal Run" 2 "Bypass" 3 "Reserved" ;
VAL_ 2149416792 P2D_CMD2_DCDCWrkMdSet_24 0 "Constant Vlotage" 1 "Constant Current" 2 "Steady Current(not greater than)" 3 "Steady Current(not less than)" ;
VAL_ 2149416792 P2D_CMD2_CommunicationState_24 0 "Normal" 1 "CAN lost" ;
VAL_ 2149416792 P2D_CMD2_DCDC_Fault_Clear_24 0 "Not Clear" 1 "Clear" ;
VAL_ 2149416792 P2D_CMD2_PCSOperationState_24 0 "Standby" 1 "Discharge" 2 "Charge" 3 "Fault" ;
VAL_ 2149416792 P2D_CMD2_DCDCLVoffControl_24 0 "不允许低压下电" 1 "允许低压下电" ;
VAL_ 2149416793 P2D_CMD2_DCDCEnable_25 0 "Disable" 1 "Enable" ;
VAL_ 2149416793 P2D_CMD2_DCDCWrkMdSwtch_25 0 "Standby" 1 "Normal Run" 2 "Bypass" 3 "Reserved" ;
VAL_ 2149416793 P2D_CMD2_DCDCWrkMdSet_25 0 "Constant Vlotage" 1 "Constant Current" 2 "Steady Current(not greater than)" 3 "Steady Current(not less than)" ;
VAL_ 2149416793 P2D_CMD2_CommunicationState_25 0 "Normal" 1 "CAN lost" ;
VAL_ 2149416793 P2D_CMD2_DCDC_Fault_Clear_25 0 "Not Clear" 1 "Clear" ;
VAL_ 2149416793 P2D_CMD2_PCSOperationState_25 0 "Standby" 1 "Discharge" 2 "Charge" 3 "Fault" ;
VAL_ 2149416793 P2D_CMD2_DCDCLVoffControl_25 0 "不允许低压下电" 1 "允许低压下电" ;
VAL_ 2149416794 P2D_CMD2_DCDCEnable_26 0 "Disable" 1 "Enable" ;
VAL_ 2149416794 P2D_CMD2_DCDCWrkMdSwtch_26 0 "Standby" 1 "Normal Run" 2 "Bypass" 3 "Reserved" ;
VAL_ 2149416794 P2D_CMD2_DCDCWrkMdSet_26 0 "Constant Vlotage" 1 "Constant Current" 2 "Steady Current(not greater than)" 3 "Steady Current(not less than)" ;
VAL_ 2149416794 P2D_CMD2_CommunicationState_26 0 "Normal" 1 "CAN lost" ;
VAL_ 2149416794 P2D_CMD2_DCDC_Fault_Clear_26 0 "Not Clear" 1 "Clear" ;
VAL_ 2149416794 P2D_CMD2_PCSOperationState_26 0 "Standby" 1 "Discharge" 2 "Charge" 3 "Fault" ;
VAL_ 2149416794 P2D_CMD2_DCDCLVoffControl_26 0 "不允许低压下电" 1 "允许低压下电" ;
VAL_ 2149416795 P2D_CMD2_DCDCEnable_27 0 "Disable" 1 "Enable" ;
VAL_ 2149416795 P2D_CMD2_DCDCWrkMdSwtch_27 0 "Standby" 1 "Normal Run" 2 "Bypass" 3 "Reserved" ;
VAL_ 2149416795 P2D_CMD2_DCDCWrkMdSet_27 0 "Constant Vlotage" 1 "Constant Current" 2 "Steady Current(not greater than)" 3 "Steady Current(not less than)" ;
VAL_ 2149416795 P2D_CMD2_CommunicationState_27 0 "Normal" 1 "CAN lost" ;
VAL_ 2149416795 P2D_CMD2_DCDC_Fault_Clear_27 0 "Not Clear" 1 "Clear" ;
VAL_ 2149416795 P2D_CMD2_PCSOperationState_27 0 "Standby" 1 "Discharge" 2 "Charge" 3 "Fault" ;
VAL_ 2149416795 P2D_CMD2_DCDCLVoffControl_27 0 "不允许低压下电" 1 "允许低压下电" ;
VAL_ 2149416796 P2D_CMD2_DCDCEnable_28 0 "Disable" 1 "Enable" ;
VAL_ 2149416796 P2D_CMD2_DCDCWrkMdSwtch_28 0 "Standby" 1 "Normal Run" 2 "Bypass" 3 "Reserved" ;
VAL_ 2149416796 P2D_CMD2_DCDCWrkMdSet_28 0 "Constant Vlotage" 1 "Constant Current" 2 "Steady Current(not greater than)" 3 "Steady Current(not less than)" ;
VAL_ 2149416796 P2D_CMD2_CommunicationState_28 0 "Normal" 1 "CAN lost" ;
VAL_ 2149416796 P2D_CMD2_DCDC_Fault_Clear_28 0 "Not Clear" 1 "Clear" ;
VAL_ 2149416796 P2D_CMD2_PCSOperationState_28 0 "Standby" 1 "Discharge" 2 "Charge" 3 "Fault" ;
VAL_ 2149416796 P2D_CMD2_DCDCLVoffControl_28 0 "不允许低压下电" 1 "允许低压下电" ;
VAL_ 2149416797 P2D_CMD2_DCDCEnable_29 0 "Disable" 1 "Enable" ;
VAL_ 2149416797 P2D_CMD2_DCDCWrkMdSwtch_29 0 "Standby" 1 "Normal Run" 2 "Bypass" 3 "Reserved" ;
VAL_ 2149416797 P2D_CMD2_DCDCWrkMdSet_29 0 "Constant Vlotage" 1 "Constant Current" 2 "Steady Current(not greater than)" 3 "Steady Current(not less than)" ;
VAL_ 2149416797 P2D_CMD2_CommunicationState_29 0 "Normal" 1 "CAN lost" ;
VAL_ 2149416797 P2D_CMD2_DCDC_Fault_Clear_29 0 "Not Clear" 1 "Clear" ;
VAL_ 2149416797 P2D_CMD2_PCSOperationState_29 0 "Standby" 1 "Discharge" 2 "Charge" 3 "Fault" ;
VAL_ 2149416797 P2D_CMD2_DCDCLVoffControl_29 0 "不允许低压下电" 1 "允许低压下电" ;
VAL_ 2149416798 P2D_CMD2_DCDCEnable_30 0 "Disable" 1 "Enable" ;
VAL_ 2149416798 P2D_CMD2_DCDCWrkMdSwtch_30 0 "Standby" 1 "Normal Run" 2 "Bypass" 3 "Reserved" ;
VAL_ 2149416798 P2D_CMD2_DCDCWrkMdSet_30 0 "Constant Vlotage" 1 "Constant Current" 2 "Steady Current(not greater than)" 3 "Steady Current(not less than)" ;
VAL_ 2149416798 P2D_CMD2_CommunicationState_30 0 "Normal" 1 "CAN lost" ;
VAL_ 2149416798 P2D_CMD2_DCDC_Fault_Clear_30 0 "Not Clear" 1 "Clear" ;
VAL_ 2149416798 P2D_CMD2_PCSOperationState_30 0 "Standby" 1 "Discharge" 2 "Charge" 3 "Fault" ;
VAL_ 2149416798 P2D_CMD2_DCDCLVoffControl_30 0 "不允许低压下电" 1 "允许低压下电" ;
VAL_ 2149416799 P2D_CMD2_DCDCEnable_31 0 "Disable" 1 "Enable" ;
VAL_ 2149416799 P2D_CMD2_DCDCWrkMdSwtch_31 0 "Standby" 1 "Normal Run" 2 "Bypass" 3 "Reserved" ;
VAL_ 2149416799 P2D_CMD2_DCDCWrkMdSet_31 0 "Constant Vlotage" 1 "Constant Current" 2 "Steady Current(not greater than)" 3 "Steady Current(not less than)" ;
VAL_ 2149416799 P2D_CMD2_CommunicationState_31 0 "Normal" 1 "CAN lost" ;
VAL_ 2149416799 P2D_CMD2_DCDC_Fault_Clear_31 0 "Not Clear" 1 "Clear" ;
VAL_ 2149416799 P2D_CMD2_PCSOperationState_31 0 "Standby" 1 "Discharge" 2 "Charge" 3 "Fault" ;
VAL_ 2149416799 P2D_CMD2_DCDCLVoffControl_31 0 "不允许低压下电" 1 "允许低压下电" ;
VAL_ 2149416800 P2D_CMD2_DCDCEnable_32 0 "Disable" 1 "Enable" ;
VAL_ 2149416800 P2D_CMD2_DCDCWrkMdSwtch_32 0 "Standby" 1 "Normal Run" 2 "Bypass" 3 "Reserved" ;
VAL_ 2149416800 P2D_CMD2_DCDCWrkMdSet_32 0 "Constant Vlotage" 1 "Constant Current" 2 "Steady Current(not greater than)" 3 "Steady Current(not less than)" ;
VAL_ 2149416800 P2D_CMD2_CommunicationState_32 0 "Normal" 1 "CAN lost" ;
VAL_ 2149416800 P2D_CMD2_DCDC_Fault_Clear_32 0 "Not Clear" 1 "Clear" ;
VAL_ 2149416800 P2D_CMD2_PCSOperationState_32 0 "Standby" 1 "Discharge" 2 "Charge" 3 "Fault" ;
VAL_ 2149416800 P2D_CMD2_DCDCLVoffControl_32 0 "不允许低压下电" 1 "允许低压下电" ;
VAL_ 2149416801 P2D_CMD2_DCDCEnable_33 0 "Disable" 1 "Enable" ;
VAL_ 2149416801 P2D_CMD2_DCDCWrkMdSwtch_33 0 "Standby" 1 "Normal Run" 2 "Bypass" 3 "Reserved" ;
VAL_ 2149416801 P2D_CMD2_DCDCWrkMdSet_33 0 "Constant Vlotage" 1 "Constant Current" 2 "Steady Current(not greater than)" 3 "Steady Current(not less than)" ;
VAL_ 2149416801 P2D_CMD2_CommunicationState_33 0 "Normal" 1 "CAN lost" ;
VAL_ 2149416801 P2D_CMD2_DCDC_Fault_Clear_33 0 "Not Clear" 1 "Clear" ;
VAL_ 2149416801 P2D_CMD2_PCSOperationState_33 0 "Standby" 1 "Discharge" 2 "Charge" 3 "Fault" ;
VAL_ 2149416801 P2D_CMD2_DCDCLVoffControl_33 0 "不允许低压下电" 1 "允许低压下电" ;
VAL_ 2149416802 P2D_CMD2_DCDCEnable_34 0 "Disable" 1 "Enable" ;
VAL_ 2149416802 P2D_CMD2_DCDCWrkMdSwtch_34 0 "Standby" 1 "Normal Run" 2 "Bypass" 3 "Reserved" ;
VAL_ 2149416802 P2D_CMD2_DCDCWrkMdSet_34 0 "Constant Vlotage" 1 "Constant Current" 2 "Steady Current(not greater than)" 3 "Steady Current(not less than)" ;
VAL_ 2149416802 P2D_CMD2_CommunicationState_34 0 "Normal" 1 "CAN lost" ;
VAL_ 2149416802 P2D_CMD2_DCDC_Fault_Clear_34 0 "Not Clear" 1 "Clear" ;
VAL_ 2149416802 P2D_CMD2_PCSOperationState_34 0 "Standby" 1 "Discharge" 2 "Charge" 3 "Fault" ;
VAL_ 2149416802 P2D_CMD2_DCDCLVoffControl_34 0 "不允许低压下电" 1 "允许低压下电" ;
VAL_ 2149416803 P2D_CMD2_DCDCEnable_35 0 "Disable" 1 "Enable" ;
VAL_ 2149416803 P2D_CMD2_DCDCWrkMdSwtch_35 0 "Standby" 1 "Normal Run" 2 "Bypass" 3 "Reserved" ;
VAL_ 2149416803 P2D_CMD2_DCDCWrkMdSet_35 0 "Constant Vlotage" 1 "Constant Current" 2 "Steady Current(not greater than)" 3 "Steady Current(not less than)" ;
VAL_ 2149416803 P2D_CMD2_CommunicationState_35 0 "Normal" 1 "CAN lost" ;
VAL_ 2149416803 P2D_CMD2_DCDC_Fault_Clear_35 0 "Not Clear" 1 "Clear" ;
VAL_ 2149416803 P2D_CMD2_PCSOperationState_35 0 "Standby" 1 "Discharge" 2 "Charge" 3 "Fault" ;
VAL_ 2149416803 P2D_CMD2_DCDCLVoffControl_35 0 "不允许低压下电" 1 "允许低压下电" ;
VAL_ 2149416804 P2D_CMD2_DCDCEnable_36 0 "Disable" 1 "Enable" ;
VAL_ 2149416804 P2D_CMD2_DCDCWrkMdSwtch_36 0 "Standby" 1 "Normal Run" 2 "Bypass" 3 "Reserved" ;
VAL_ 2149416804 P2D_CMD2_DCDCWrkMdSet_36 0 "Constant Vlotage" 1 "Constant Current" 2 "Steady Current(not greater than)" 3 "Steady Current(not less than)" ;
VAL_ 2149416804 P2D_CMD2_CommunicationState_36 0 "Normal" 1 "CAN lost" ;
VAL_ 2149416804 P2D_CMD2_DCDC_Fault_Clear_36 0 "Not Clear" 1 "Clear" ;
VAL_ 2149416804 P2D_CMD2_PCSOperationState_36 0 "Standby" 1 "Discharge" 2 "Charge" 3 "Fault" ;
VAL_ 2149416804 P2D_CMD2_DCDCLVoffControl_36 0 "不允许低压下电" 1 "允许低压下电" ;
VAL_ 2149416805 P2D_CMD2_DCDCEnable_37 0 "Disable" 1 "Enable" ;
VAL_ 2149416805 P2D_CMD2_DCDCWrkMdSwtch_37 0 "Standby" 1 "Normal Run" 2 "Bypass" 3 "Reserved" ;
VAL_ 2149416805 P2D_CMD2_DCDCWrkMdSet_37 0 "Constant Vlotage" 1 "Constant Current" 2 "Steady Current(not greater than)" 3 "Steady Current(not less than)" ;
VAL_ 2149416805 P2D_CMD2_CommunicationState_37 0 "Normal" 1 "CAN lost" ;
VAL_ 2149416805 P2D_CMD2_DCDC_Fault_Clear_37 0 "Not Clear" 1 "Clear" ;
VAL_ 2149416805 P2D_CMD2_PCSOperationState_37 0 "Standby" 1 "Discharge" 2 "Charge" 3 "Fault" ;
VAL_ 2149416805 P2D_CMD2_DCDCLVoffControl_37 0 "不允许低压下电" 1 "允许低压下电" ;
VAL_ 2149416806 P2D_CMD2_DCDCEnable_38 0 "Disable" 1 "Enable" ;
VAL_ 2149416806 P2D_CMD2_DCDCWrkMdSwtch_38 0 "Standby" 1 "Normal Run" 2 "Bypass" 3 "Reserved" ;
VAL_ 2149416806 P2D_CMD2_DCDCWrkMdSet_38 0 "Constant Vlotage" 1 "Constant Current" 2 "Steady Current(not greater than)" 3 "Steady Current(not less than)" ;
VAL_ 2149416806 P2D_CMD2_CommunicationState_38 0 "Normal" 1 "CAN lost" ;
VAL_ 2149416806 P2D_CMD2_DCDC_Fault_Clear_38 0 "Not Clear" 1 "Clear" ;
VAL_ 2149416806 P2D_CMD2_PCSOperationState_38 0 "Standby" 1 "Discharge" 2 "Charge" 3 "Fault" ;
VAL_ 2149416806 P2D_CMD2_DCDCLVoffControl_38 0 "不允许低压下电" 1 "允许低压下电" ;
VAL_ 2149416807 P2D_CMD2_DCDCEnable_39 0 "Disable" 1 "Enable" ;
VAL_ 2149416807 P2D_CMD2_DCDCWrkMdSwtch_39 0 "Standby" 1 "Normal Run" 2 "Bypass" 3 "Reserved" ;
VAL_ 2149416807 P2D_CMD2_DCDCWrkMdSet_39 0 "Constant Vlotage" 1 "Constant Current" 2 "Steady Current(not greater than)" 3 "Steady Current(not less than)" ;
VAL_ 2149416807 P2D_CMD2_CommunicationState_39 0 "Normal" 1 "CAN lost" ;
VAL_ 2149416807 P2D_CMD2_DCDC_Fault_Clear_39 0 "Not Clear" 1 "Clear" ;
VAL_ 2149416807 P2D_CMD2_PCSOperationState_39 0 "Standby" 1 "Discharge" 2 "Charge" 3 "Fault" ;
VAL_ 2149416807 P2D_CMD2_DCDCLVoffControl_39 0 "不允许低压下电" 1 "允许低压下电" ;
VAL_ 2149416808 P2D_CMD2_DCDCEnable_40 0 "Disable" 1 "Enable" ;
VAL_ 2149416808 P2D_CMD2_DCDCWrkMdSwtch_40 0 "Standby" 1 "Normal Run" 2 "Bypass" 3 "Reserved" ;
VAL_ 2149416808 P2D_CMD2_DCDCWrkMdSet_40 0 "Constant Vlotage" 1 "Constant Current" 2 "Steady Current(not greater than)" 3 "Steady Current(not less than)" ;
VAL_ 2149416808 P2D_CMD2_CommunicationState_40 0 "Normal" 1 "CAN lost" ;
VAL_ 2149416808 P2D_CMD2_DCDC_Fault_Clear_40 0 "Not Clear" 1 "Clear" ;
VAL_ 2149416808 P2D_CMD2_PCSOperationState_40 0 "Standby" 1 "Discharge" 2 "Charge" 3 "Fault" ;
VAL_ 2149416808 P2D_CMD2_DCDCLVoffControl_40 0 "不允许低压下电" 1 "允许低压下电" ;
VAL_ 2149416809 P2D_CMD2_DCDCEnable_41 0 "Disable" 1 "Enable" ;
VAL_ 2149416809 P2D_CMD2_DCDCWrkMdSwtch_41 0 "Standby" 1 "Normal Run" 2 "Bypass" 3 "Reserved" ;
VAL_ 2149416809 P2D_CMD2_DCDCWrkMdSet_41 0 "Constant Vlotage" 1 "Constant Current" 2 "Steady Current(not greater than)" 3 "Steady Current(not less than)" ;
VAL_ 2149416809 P2D_CMD2_CommunicationState_41 0 "Normal" 1 "CAN lost" ;
VAL_ 2149416809 P2D_CMD2_DCDC_Fault_Clear_41 0 "Not Clear" 1 "Clear" ;
VAL_ 2149416809 P2D_CMD2_PCSOperationState_41 0 "Standby" 1 "Discharge" 2 "Charge" 3 "Fault" ;
VAL_ 2149416809 P2D_CMD2_DCDCLVoffControl_41 0 "不允许低压下电" 1 "允许低压下电" ;
VAL_ 2149416810 P2D_CMD2_DCDCEnable_42 0 "Disable" 1 "Enable" ;
VAL_ 2149416810 P2D_CMD2_DCDCWrkMdSwtch_42 0 "Standby" 1 "Normal Run" 2 "Bypass" 3 "Reserved" ;
VAL_ 2149416810 P2D_CMD2_DCDCWrkMdSet_42 0 "Constant Vlotage" 1 "Constant Current" 2 "Steady Current(not greater than)" 3 "Steady Current(not less than)" ;
VAL_ 2149416810 P2D_CMD2_CommunicationState_42 0 "Normal" 1 "CAN lost" ;
VAL_ 2149416810 P2D_CMD2_DCDC_Fault_Clear_42 0 "Not Clear" 1 "Clear" ;
VAL_ 2149416810 P2D_CMD2_PCSOperationState_42 0 "Standby" 1 "Discharge" 2 "Charge" 3 "Fault" ;
VAL_ 2149416810 P2D_CMD2_DCDCLVoffControl_42 0 "不允许低压下电" 1 "允许低压下电" ;
VAL_ 2149416811 P2D_CMD2_DCDCEnable_43 0 "Disable" 1 "Enable" ;
VAL_ 2149416811 P2D_CMD2_DCDCWrkMdSwtch_43 0 "Standby" 1 "Normal Run" 2 "Bypass" 3 "Reserved" ;
VAL_ 2149416811 P2D_CMD2_DCDCWrkMdSet_43 0 "Constant Vlotage" 1 "Constant Current" 2 "Steady Current(not greater than)" 3 "Steady Current(not less than)" ;
VAL_ 2149416811 P2D_CMD2_CommunicationState_43 0 "Normal" 1 "CAN lost" ;
VAL_ 2149416811 P2D_CMD2_DCDC_Fault_Clear_43 0 "Not Clear" 1 "Clear" ;
VAL_ 2149416811 P2D_CMD2_PCSOperationState_43 0 "Standby" 1 "Discharge" 2 "Charge" 3 "Fault" ;
VAL_ 2149416811 P2D_CMD2_DCDCLVoffControl_43 0 "不允许低压下电" 1 "允许低压下电" ;
VAL_ 2149416812 P2D_CMD2_DCDCEnable_44 0 "Disable" 1 "Enable" ;
VAL_ 2149416812 P2D_CMD2_DCDCWrkMdSwtch_44 0 "Standby" 1 "Normal Run" 2 "Bypass" 3 "Reserved" ;
VAL_ 2149416812 P2D_CMD2_DCDCWrkMdSet_44 0 "Constant Vlotage" 1 "Constant Current" 2 "Steady Current(not greater than)" 3 "Steady Current(not less than)" ;
VAL_ 2149416812 P2D_CMD2_CommunicationState_44 0 "Normal" 1 "CAN lost" ;
VAL_ 2149416812 P2D_CMD2_DCDC_Fault_Clear_44 0 "Not Clear" 1 "Clear" ;
VAL_ 2149416812 P2D_CMD2_PCSOperationState_44 0 "Standby" 1 "Discharge" 2 "Charge" 3 "Fault" ;
VAL_ 2149416812 P2D_CMD2_DCDCLVoffControl_44 0 "不允许低压下电" 1 "允许低压下电" ;
VAL_ 2149416813 P2D_CMD2_DCDCEnable_45 0 "Disable" 1 "Enable" ;
VAL_ 2149416813 P2D_CMD2_DCDCWrkMdSwtch_45 0 "Standby" 1 "Normal Run" 2 "Bypass" 3 "Reserved" ;
VAL_ 2149416813 P2D_CMD2_DCDCWrkMdSet_45 0 "Constant Vlotage" 1 "Constant Current" 2 "Steady Current(not greater than)" 3 "Steady Current(not less than)" ;
VAL_ 2149416813 P2D_CMD2_CommunicationState_45 0 "Normal" 1 "CAN lost" ;
VAL_ 2149416813 P2D_CMD2_DCDC_Fault_Clear_45 0 "Not Clear" 1 "Clear" ;
VAL_ 2149416813 P2D_CMD2_PCSOperationState_45 0 "Standby" 1 "Discharge" 2 "Charge" 3 "Fault" ;
VAL_ 2149416813 P2D_CMD2_DCDCLVoffControl_45 0 "不允许低压下电" 1 "允许低压下电" ;
VAL_ 2149416814 P2D_CMD2_DCDCEnable_46 0 "Disable" 1 "Enable" ;
VAL_ 2149416814 P2D_CMD2_DCDCWrkMdSwtch_46 0 "Standby" 1 "Normal Run" 2 "Bypass" 3 "Reserved" ;
VAL_ 2149416814 P2D_CMD2_DCDCWrkMdSet_46 0 "Constant Vlotage" 1 "Constant Current" 2 "Steady Current(not greater than)" 3 "Steady Current(not less than)" ;
VAL_ 2149416814 P2D_CMD2_CommunicationState_46 0 "Normal" 1 "CAN lost" ;
VAL_ 2149416814 P2D_CMD2_DCDC_Fault_Clear_46 0 "Not Clear" 1 "Clear" ;
VAL_ 2149416814 P2D_CMD2_PCSOperationState_46 0 "Standby" 1 "Discharge" 2 "Charge" 3 "Fault" ;
VAL_ 2149416814 P2D_CMD2_DCDCLVoffControl_46 0 "不允许低压下电" 1 "允许低压下电" ;
VAL_ 2149416815 P2D_CMD2_DCDCEnable_47 0 "Disable" 1 "Enable" ;
VAL_ 2149416815 P2D_CMD2_DCDCWrkMdSwtch_47 0 "Standby" 1 "Normal Run" 2 "Bypass" 3 "Reserved" ;
VAL_ 2149416815 P2D_CMD2_DCDCWrkMdSet_47 0 "Constant Vlotage" 1 "Constant Current" 2 "Steady Current(not greater than)" 3 "Steady Current(not less than)" ;
VAL_ 2149416815 P2D_CMD2_CommunicationState_47 0 "Normal" 1 "CAN lost" ;
VAL_ 2149416815 P2D_CMD2_DCDC_Fault_Clear_47 0 "Not Clear" 1 "Clear" ;
VAL_ 2149416815 P2D_CMD2_PCSOperationState_47 0 "Standby" 1 "Discharge" 2 "Charge" 3 "Fault" ;
VAL_ 2149416815 P2D_CMD2_DCDCLVoffControl_47 0 "不允许低压下电" 1 "允许低压下电" ;
VAL_ 2149416816 P2D_CMD2_DCDCEnable_48 0 "Disable" 1 "Enable" ;
VAL_ 2149416816 P2D_CMD2_DCDCWrkMdSwtch_48 0 "Standby" 1 "Normal Run" 2 "Bypass" 3 "Reserved" ;
VAL_ 2149416816 P2D_CMD2_DCDCWrkMdSet_48 0 "Constant Vlotage" 1 "Constant Current" 2 "Steady Current(not greater than)" 3 "Steady Current(not less than)" ;
VAL_ 2149416816 P2D_CMD2_CommunicationState_48 0 "Normal" 1 "CAN lost" ;
VAL_ 2149416816 P2D_CMD2_DCDC_Fault_Clear_48 0 "Not Clear" 1 "Clear" ;
VAL_ 2149416816 P2D_CMD2_PCSOperationState_48 0 "Standby" 1 "Discharge" 2 "Charge" 3 "Fault" ;
VAL_ 2149416816 P2D_CMD2_DCDCLVoffControl_48 0 "不允许低压下电" 1 "允许低压下电" ;
VAL_ 2149416817 P2D_CMD2_DCDCEnable_49 0 "Disable" 1 "Enable" ;
VAL_ 2149416817 P2D_CMD2_DCDCWrkMdSwtch_49 0 "Standby" 1 "Normal Run" 2 "Bypass" 3 "Reserved" ;
VAL_ 2149416817 P2D_CMD2_DCDCWrkMdSet_49 0 "Constant Vlotage" 1 "Constant Current" 2 "Steady Current(not greater than)" 3 "Steady Current(not less than)" ;
VAL_ 2149416817 P2D_CMD2_CommunicationState_49 0 "Normal" 1 "CAN lost" ;
VAL_ 2149416817 P2D_CMD2_DCDC_Fault_Clear_49 0 "Not Clear" 1 "Clear" ;
VAL_ 2149416817 P2D_CMD2_PCSOperationState_49 0 "Standby" 1 "Discharge" 2 "Charge" 3 "Fault" ;
VAL_ 2149416817 P2D_CMD2_DCDCLVoffControl_49 0 "不允许低压下电" 1 "允许低压下电" ;
VAL_ 2149416818 P2D_CMD2_DCDCEnable_50 0 "Disable" 1 "Enable" ;
VAL_ 2149416818 P2D_CMD2_DCDCWrkMdSwtch_50 0 "Standby" 1 "Normal Run" 2 "Bypass" 3 "Reserved" ;
VAL_ 2149416818 P2D_CMD2_DCDCWrkMdSet_50 0 "Constant Vlotage" 1 "Constant Current" 2 "Steady Current(not greater than)" 3 "Steady Current(not less than)" ;
VAL_ 2149416818 P2D_CMD2_CommunicationState_50 0 "Normal" 1 "CAN lost" ;
VAL_ 2149416818 P2D_CMD2_DCDC_Fault_Clear_50 0 "Not Clear" 1 "Clear" ;
VAL_ 2149416818 P2D_CMD2_PCSOperationState_50 0 "Standby" 1 "Discharge" 2 "Charge" 3 "Fault" ;
VAL_ 2149416818 P2D_CMD2_DCDCLVoffControl_50 0 "不允许低压下电" 1 "允许低压下电" ;
VAL_ 2149416819 P2D_CMD2_DCDCEnable_51 0 "Disable" 1 "Enable" ;
VAL_ 2149416819 P2D_CMD2_DCDCWrkMdSwtch_51 0 "Standby" 1 "Normal Run" 2 "Bypass" 3 "Reserved" ;
VAL_ 2149416819 P2D_CMD2_DCDCWrkMdSet_51 0 "Constant Vlotage" 1 "Constant Current" 2 "Steady Current(not greater than)" 3 "Steady Current(not less than)" ;
VAL_ 2149416819 P2D_CMD2_CommunicationState_51 0 "Normal" 1 "CAN lost" ;
VAL_ 2149416819 P2D_CMD2_DCDC_Fault_Clear_51 0 "Not Clear" 1 "Clear" ;
VAL_ 2149416819 P2D_CMD2_PCSOperationState_51 0 "Standby" 1 "Discharge" 2 "Charge" 3 "Fault" ;
VAL_ 2149416819 P2D_CMD2_DCDCLVoffControl_51 0 "不允许低压下电" 1 "允许低压下电" ;
VAL_ 2149416820 P2D_CMD2_DCDCEnable_52 0 "Disable" 1 "Enable" ;
VAL_ 2149416820 P2D_CMD2_DCDCWrkMdSwtch_52 0 "Standby" 1 "Normal Run" 2 "Bypass" 3 "Reserved" ;
VAL_ 2149416820 P2D_CMD2_DCDCWrkMdSet_52 0 "Constant Vlotage" 1 "Constant Current" 2 "Steady Current(not greater than)" 3 "Steady Current(not less than)" ;
VAL_ 2149416820 P2D_CMD2_CommunicationState_52 0 "Normal" 1 "CAN lost" ;
VAL_ 2149416820 P2D_CMD2_DCDC_Fault_Clear_52 0 "Not Clear" 1 "Clear" ;
VAL_ 2149416820 P2D_CMD2_PCSOperationState_52 0 "Standby" 1 "Discharge" 2 "Charge" 3 "Fault" ;
VAL_ 2149416820 P2D_CMD2_DCDCLVoffControl_52 0 "不允许低压下电" 1 "允许低压下电" ;
VAL_ 2149416821 P2D_CMD2_DCDCEnable_53 0 "Disable" 1 "Enable" ;
VAL_ 2149416821 P2D_CMD2_DCDCWrkMdSwtch_53 0 "Standby" 1 "Normal Run" 2 "Bypass" 3 "Reserved" ;
VAL_ 2149416821 P2D_CMD2_DCDCWrkMdSet_53 0 "Constant Vlotage" 1 "Constant Current" 2 "Steady Current(not greater than)" 3 "Steady Current(not less than)" ;
VAL_ 2149416821 P2D_CMD2_CommunicationState_53 0 "Normal" 1 "CAN lost" ;
VAL_ 2149416821 P2D_CMD2_DCDC_Fault_Clear_53 0 "Not Clear" 1 "Clear" ;
VAL_ 2149416821 P2D_CMD2_PCSOperationState_53 0 "Standby" 1 "Discharge" 2 "Charge" 3 "Fault" ;
VAL_ 2149416821 P2D_CMD2_DCDCLVoffControl_53 0 "不允许低压下电" 1 "允许低压下电" ;
VAL_ 2149416822 P2D_CMD2_DCDCEnable_54 0 "Disable" 1 "Enable" ;
VAL_ 2149416822 P2D_CMD2_DCDCWrkMdSwtch_54 0 "Standby" 1 "Normal Run" 2 "Bypass" 3 "Reserved" ;
VAL_ 2149416822 P2D_CMD2_DCDCWrkMdSet_54 0 "Constant Vlotage" 1 "Constant Current" 2 "Steady Current(not greater than)" 3 "Steady Current(not less than)" ;
VAL_ 2149416822 P2D_CMD2_CommunicationState_54 0 "Normal" 1 "CAN lost" ;
VAL_ 2149416822 P2D_CMD2_DCDC_Fault_Clear_54 0 "Not Clear" 1 "Clear" ;
VAL_ 2149416822 P2D_CMD2_PCSOperationState_54 0 "Standby" 1 "Discharge" 2 "Charge" 3 "Fault" ;
VAL_ 2149416822 P2D_CMD2_DCDCLVoffControl_54 0 "不允许低压下电" 1 "允许低压下电" ;
VAL_ 2149416823 P2D_CMD2_DCDCEnable_55 0 "Disable" 1 "Enable" ;
VAL_ 2149416823 P2D_CMD2_DCDCWrkMdSwtch_55 0 "Standby" 1 "Normal Run" 2 "Bypass" 3 "Reserved" ;
VAL_ 2149416823 P2D_CMD2_DCDCWrkMdSet_55 0 "Constant Vlotage" 1 "Constant Current" 2 "Steady Current(not greater than)" 3 "Steady Current(not less than)" ;
VAL_ 2149416823 P2D_CMD2_CommunicationState_55 0 "Normal" 1 "CAN lost" ;
VAL_ 2149416823 P2D_CMD2_DCDC_Fault_Clear_55 0 "Not Clear" 1 "Clear" ;
VAL_ 2149416823 P2D_CMD2_PCSOperationState_55 0 "Standby" 1 "Discharge" 2 "Charge" 3 "Fault" ;
VAL_ 2149416823 P2D_CMD2_DCDCLVoffControl_55 0 "不允许低压下电" 1 "允许低压下电" ;
VAL_ 2149416824 P2D_CMD2_DCDCEnable_56 0 "Disable" 1 "Enable" ;
VAL_ 2149416824 P2D_CMD2_DCDCWrkMdSwtch_56 0 "Standby" 1 "Normal Run" 2 "Bypass" 3 "Reserved" ;
VAL_ 2149416824 P2D_CMD2_DCDCWrkMdSet_56 0 "Constant Vlotage" 1 "Constant Current" 2 "Steady Current(not greater than)" 3 "Steady Current(not less than)" ;
VAL_ 2149416824 P2D_CMD2_CommunicationState_56 0 "Normal" 1 "CAN lost" ;
VAL_ 2149416824 P2D_CMD2_DCDC_Fault_Clear_56 0 "Not Clear" 1 "Clear" ;
VAL_ 2149416824 P2D_CMD2_PCSOperationState_56 0 "Standby" 1 "Discharge" 2 "Charge" 3 "Fault" ;
VAL_ 2149416824 P2D_CMD2_DCDCLVoffControl_56 0 "不允许低压下电" 1 "允许低压下电" ;
VAL_ 2149416825 P2D_CMD2_DCDCEnable_57 0 "Disable" 1 "Enable" ;
VAL_ 2149416825 P2D_CMD2_DCDCWrkMdSwtch_57 0 "Standby" 1 "Normal Run" 2 "Bypass" 3 "Reserved" ;
VAL_ 2149416825 P2D_CMD2_DCDCWrkMdSet_57 0 "Constant Vlotage" 1 "Constant Current" 2 "Steady Current(not greater than)" 3 "Steady Current(not less than)" ;
VAL_ 2149416825 P2D_CMD2_CommunicationState_57 0 "Normal" 1 "CAN lost" ;
VAL_ 2149416825 P2D_CMD2_DCDC_Fault_Clear_57 0 "Not Clear" 1 "Clear" ;
VAL_ 2149416825 P2D_CMD2_PCSOperationState_57 0 "Standby" 1 "Discharge" 2 "Charge" 3 "Fault" ;
VAL_ 2149416825 P2D_CMD2_DCDCLVoffControl_57 0 "不允许低压下电" 1 "允许低压下电" ;
VAL_ 2149416826 P2D_CMD2_DCDCEnable_58 0 "Disable" 1 "Enable" ;
VAL_ 2149416826 P2D_CMD2_DCDCWrkMdSwtch_58 0 "Standby" 1 "Normal Run" 2 "Bypass" 3 "Reserved" ;
VAL_ 2149416826 P2D_CMD2_DCDCWrkMdSet_58 0 "Constant Vlotage" 1 "Constant Current" 2 "Steady Current(not greater than)" 3 "Steady Current(not less than)" ;
VAL_ 2149416826 P2D_CMD2_CommunicationState_58 0 "Normal" 1 "CAN lost" ;
VAL_ 2149416826 P2D_CMD2_DCDC_Fault_Clear_58 0 "Not Clear" 1 "Clear" ;
VAL_ 2149416826 P2D_CMD2_PCSOperationState_58 0 "Standby" 1 "Discharge" 2 "Charge" 3 "Fault" ;
VAL_ 2149416826 P2D_CMD2_DCDCLVoffControl_58 0 "不允许低压下电" 1 "允许低压下电" ;
VAL_ 2149416827 P2D_CMD2_DCDCEnable_59 0 "Disable" 1 "Enable" ;
VAL_ 2149416827 P2D_CMD2_DCDCWrkMdSwtch_59 0 "Standby" 1 "Normal Run" 2 "Bypass" 3 "Reserved" ;
VAL_ 2149416827 P2D_CMD2_DCDCWrkMdSet_59 0 "Constant Vlotage" 1 "Constant Current" 2 "Steady Current(not greater than)" 3 "Steady Current(not less than)" ;
VAL_ 2149416827 P2D_CMD2_CommunicationState_59 0 "Normal" 1 "CAN lost" ;
VAL_ 2149416827 P2D_CMD2_DCDC_Fault_Clear_59 0 "Not Clear" 1 "Clear" ;
VAL_ 2149416827 P2D_CMD2_PCSOperationState_59 0 "Standby" 1 "Discharge" 2 "Charge" 3 "Fault" ;
VAL_ 2149416827 P2D_CMD2_DCDCLVoffControl_59 0 "不允许低压下电" 1 "允许低压下电" ;
VAL_ 2149416828 P2D_CMD2_DCDCEnable_60 0 "Disable" 1 "Enable" ;
VAL_ 2149416828 P2D_CMD2_DCDCWrkMdSwtch_60 0 "Standby" 1 "Normal Run" 2 "Bypass" 3 "Reserved" ;
VAL_ 2149416828 P2D_CMD2_DCDCWrkMdSet_60 0 "Constant Vlotage" 1 "Constant Current" 2 "Steady Current(not greater than)" 3 "Steady Current(not less than)" ;
VAL_ 2149416828 P2D_CMD2_CommunicationState_60 0 "Normal" 1 "CAN lost" ;
VAL_ 2149416828 P2D_CMD2_DCDC_Fault_Clear_60 0 "Not Clear" 1 "Clear" ;
VAL_ 2149416828 P2D_CMD2_PCSOperationState_60 0 "Standby" 1 "Discharge" 2 "Charge" 3 "Fault" ;
VAL_ 2149416828 P2D_CMD2_DCDCLVoffControl_60 0 "不允许低压下电" 1 "允许低压下电" ;
VAL_ 2149416829 P2D_CMD2_DCDCEnable_61 0 "Disable" 1 "Enable" ;
VAL_ 2149416829 P2D_CMD2_DCDCWrkMdSwtch_61 0 "Standby" 1 "Normal Run" 2 "Bypass" 3 "Reserved" ;
VAL_ 2149416829 P2D_CMD2_DCDCWrkMdSet_61 0 "Constant Vlotage" 1 "Constant Current" 2 "Steady Current(not greater than)" 3 "Steady Current(not less than)" ;
VAL_ 2149416829 P2D_CMD2_CommunicationState_61 0 "Normal" 1 "CAN lost" ;
VAL_ 2149416829 P2D_CMD2_DCDC_Fault_Clear_61 0 "Not Clear" 1 "Clear" ;
VAL_ 2149416829 P2D_CMD2_PCSOperationState_61 0 "Standby" 1 "Discharge" 2 "Charge" 3 "Fault" ;
VAL_ 2149416829 P2D_CMD2_DCDCLVoffControl_61 0 "不允许低压下电" 1 "允许低压下电" ;
VAL_ 2149416830 P2D_CMD2_DCDCEnable_62 0 "Disable" 1 "Enable" ;
VAL_ 2149416830 P2D_CMD2_DCDCWrkMdSwtch_62 0 "Standby" 1 "Normal Run" 2 "Bypass" 3 "Reserved" ;
VAL_ 2149416830 P2D_CMD2_DCDCWrkMdSet_62 0 "Constant Vlotage" 1 "Constant Current" 2 "Steady Current(not greater than)" 3 "Steady Current(not less than)" ;
VAL_ 2149416830 P2D_CMD2_CommunicationState_62 0 "Normal" 1 "CAN lost" ;
VAL_ 2149416830 P2D_CMD2_DCDC_Fault_Clear_62 0 "Not Clear" 1 "Clear" ;
VAL_ 2149416830 P2D_CMD2_PCSOperationState_62 0 "Standby" 1 "Discharge" 2 "Charge" 3 "Fault" ;
VAL_ 2149416830 P2D_CMD2_DCDCLVoffControl_62 0 "不允许低压下电" 1 "允许低压下电" ;
VAL_ 2149416831 P2D_CMD2_DCDCEnable_63 0 "Disable" 1 "Enable" ;
VAL_ 2149416831 P2D_CMD2_DCDCWrkMdSwtch_63 0 "Standby" 1 "Normal Run" 2 "Bypass" 3 "Reserved" ;
VAL_ 2149416831 P2D_CMD2_DCDCWrkMdSet_63 0 "Constant Vlotage" 1 "Constant Current" 2 "Steady Current(not greater than)" 3 "Steady Current(not less than)" ;
VAL_ 2149416831 P2D_CMD2_CommunicationState_63 0 "Normal" 1 "CAN lost" ;
VAL_ 2149416831 P2D_CMD2_DCDC_Fault_Clear_63 0 "Not Clear" 1 "Clear" ;
VAL_ 2149416831 P2D_CMD2_PCSOperationState_63 0 "Standby" 1 "Discharge" 2 "Charge" 3 "Fault" ;
VAL_ 2149416831 P2D_CMD2_DCDCLVoffControl_63 0 "不允许低压下电" 1 "允许低压下电" ;
VAL_ 2149482478 P2D_Cfg5_DCDC_Add 65 "0x41, DCDC1" 66 "0x42, DCDC2" 67 "0x43, DCDC3" 68 "0x44, DCDC4" 69 "0x45, DCDC5" ;
VAL_ 2149547841 D2P_ALARM_EnvExtreOverTemp 0 "No Alarm" 1 "Alarm Occur" ;
VAL_ 2149547841 D2P_ALARM_EnvOverTemp 0 "No Alarm" 1 "Alarm Occur" ;
VAL_ 2149547841 D2P_ALARM_MosOverTemp 0 "No Alarm" 1 "Alarm Occur" ;
VAL_ 2149547841 D2P_ALARM_MosExtreOverTemp 0 "No Alarm" 1 "Alarm Occur" ;
VAL_ 2149547841 D2P_ALARM_HighSideOverVolt 0 "No Alarm" 1 "Alarm Occur" ;
VAL_ 2149547841 D2P_ALARM_HighSideUnderVolt 0 "No Alarm" 1 "Alarm Occur" ;
VAL_ 2149547841 D2P_ALARM_LowSideOverVolt 0 "No Alarm" 1 "Alarm Occur" ;
VAL_ 2149547841 D2P_ALARM_HighSideOverCurr 0 "No Alarm" 1 "Alarm Occur" ;
VAL_ 2149547841 D2P_ALARM_LowSideOverCurr_HW 0 "No Alarm" 1 "Alarm Occur" ;
VAL_ 2149547841 D2P_ALARM_LowSideOverCurr_SW 0 "No Alarm" 1 "Alarm Occur" ;
VAL_ 2149547841 D2P_ALARM_SecSideOverCurr_HW 0 "No Alarm" 1 "Alarm Occur" ;
VAL_ 2149547841 D2P_ALARM_SecSideOverCurr_SW 0 "No Alarm" 1 "Alarm Occur" ;
VAL_ 2149547841 D2P_ALARM_PriSideOverCurr_HW 0 "No Alarm" 1 "Alarm Occur" ;
VAL_ 2149547841 D2P_ALARM_PriSideOverCurr_SW 0 "No Alarm" 1 "Alarm Occur" ;
VAL_ 2149547841 D2P_ALARM_LowPowerSupplyErr 0 "No Alarm" 1 "Alarm Occur" ;
VAL_ 2149547841 D2P_ALARM_MBMUComErr 0 "No Alarm" 1 "Alarm Occur" ;
VAL_ 2149547841 D2P_ALARM_DCDCMsTeSaplgErr 0 "No Alarm" 1 "Alarm Occur" ;
VAL_ 2149547841 D2P_ALARM_DCDCTeSaplgErr 0 "No Alarm" 1 "Alarm Occur" ;
VAL_ 2149547841 D2P_ALARM_VoltSamplingErr 0 "No Alarm" 1 "Alarm Occur" ;
VAL_ 2149547841 D2P_ALARM_HgSdCuSaplgErr 0 "No Alarm" 1 "Alarm Occur" ;
VAL_ 2149547841 D2P_ALARM_CtrlCurrSamplingErr 0 "No Alarm" 1 "Alarm Occur" ;
VAL_ 2149547841 D2P_ALARM_BypassFail 0 "No Alarm" 1 "Alarm Occur" ;
VAL_ 2149547841 D2P_ALARM_Reserve1 0 "No Alarm" 1 "Alarm Occur" ;
VAL_ 2149547841 D2P_ALARM_Reserve2 0 "No Alarm" 1 "Alarm Occur" ;
VAL_ 2149547841 D2P_ALARM_Reserve3 0 "No Alarm" 1 "Alarm Occur" ;
VAL_ 2149547841 D2P_ALARM_Reserve4 0 "No Alarm" 1 "Alarm Occur" ;
VAL_ 2149547841 D2P_ALARM_Reserve5 0 "No Alarm" 1 "Alarm Occur" ;
VAL_ 2149547841 D2P_ALARM_Reserve6 0 "No Alarm" 1 "Alarm Occur" ;
VAL_ 2149547841 D2P_ALARM_Reserve7 0 "No Alarm" 1 "Alarm Occur" ;
VAL_ 2149547841 D2P_ALARM_Reserve8 0 "No Alarm" 1 "Alarm Occur" ;
VAL_ 2149547841 D2P_ALARM_Reserve9 0 "No Alarm" 1 "Alarm Occur" ;
VAL_ 2149547841 D2P_ALARM_Reserve10 0 "No Alarm" 1 "Alarm Occur" ;
VAL_ 2149547841 D2P_ALARM_Reserve11 0 "No Alarm" 1 "Alarm Occur" ;
VAL_ 2149547842 D2P_ALARM_EnvExtreOverTemp 0 "No Alarm" 1 "Alarm Occur" ;
VAL_ 2149547842 D2P_ALARM_EnvOverTemp 0 "No Alarm" 1 "Alarm Occur" ;
VAL_ 2149547842 D2P_ALARM_MosOverTemp 0 "No Alarm" 1 "Alarm Occur" ;
VAL_ 2149547842 D2P_ALARM_MosExtreOverTemp 0 "No Alarm" 1 "Alarm Occur" ;
VAL_ 2149547842 D2P_ALARM_HighSideOverVolt 0 "No Alarm" 1 "Alarm Occur" ;
VAL_ 2149547842 D2P_ALARM_HighSideUnderVolt 0 "No Alarm" 1 "Alarm Occur" ;
VAL_ 2149547842 D2P_ALARM_LowSideOverVolt 0 "No Alarm" 1 "Alarm Occur" ;
VAL_ 2149547842 D2P_ALARM_HighSideOverCurr 0 "No Alarm" 1 "Alarm Occur" ;
VAL_ 2149547842 D2P_ALARM_LowSideOverCurr_HW 0 "No Alarm" 1 "Alarm Occur" ;
VAL_ 2149547842 D2P_ALARM_LowSideOverCurr_SW 0 "No Alarm" 1 "Alarm Occur" ;
VAL_ 2149547842 D2P_ALARM_SecSideOverCurr_HW 0 "No Alarm" 1 "Alarm Occur" ;
VAL_ 2149547842 D2P_ALARM_SecSideOverCurr_SW 0 "No Alarm" 1 "Alarm Occur" ;
VAL_ 2149547842 D2P_ALARM_PriSideOverCurr_HW 0 "No Alarm" 1 "Alarm Occur" ;
VAL_ 2149547842 D2P_ALARM_PriSideOverCurr_SW 0 "No Alarm" 1 "Alarm Occur" ;
VAL_ 2149547842 D2P_ALARM_LowPowerSupplyErr 0 "No Alarm" 1 "Alarm Occur" ;
VAL_ 2149547842 D2P_ALARM_MBMUComErr 0 "No Alarm" 1 "Alarm Occur" ;
VAL_ 2149547842 D2P_ALARM_DCDCMsTeSaplgErr 0 "No Alarm" 1 "Alarm Occur" ;
VAL_ 2149547842 D2P_ALARM_DCDCTeSaplgErr 0 "No Alarm" 1 "Alarm Occur" ;
VAL_ 2149547842 D2P_ALARM_VoltSamplingErr 0 "No Alarm" 1 "Alarm Occur" ;
VAL_ 2149547842 D2P_ALARM_HgSdCuSaplgErr 0 "No Alarm" 1 "Alarm Occur" ;
VAL_ 2149547842 D2P_ALARM_CtrlCurrSamplingErr 0 "No Alarm" 1 "Alarm Occur" ;
VAL_ 2149547842 D2P_ALARM_BypassFail 0 "No Alarm" 1 "Alarm Occur" ;
VAL_ 2149547842 D2P_ALARM_Reserve1 0 "No Alarm" 1 "Alarm Occur" ;
VAL_ 2149547842 D2P_ALARM_Reserve2 0 "No Alarm" 1 "Alarm Occur" ;
VAL_ 2149547842 D2P_ALARM_Reserve3 0 "No Alarm" 1 "Alarm Occur" ;
VAL_ 2149547842 D2P_ALARM_Reserve4 0 "No Alarm" 1 "Alarm Occur" ;
VAL_ 2149547842 D2P_ALARM_Reserve5 0 "No Alarm" 1 "Alarm Occur" ;
VAL_ 2149547842 D2P_ALARM_Reserve6 0 "No Alarm" 1 "Alarm Occur" ;
VAL_ 2149547842 D2P_ALARM_Reserve7 0 "No Alarm" 1 "Alarm Occur" ;
VAL_ 2149547842 D2P_ALARM_Reserve8 0 "No Alarm" 1 "Alarm Occur" ;
VAL_ 2149547842 D2P_ALARM_Reserve9 0 "No Alarm" 1 "Alarm Occur" ;
VAL_ 2149547842 D2P_ALARM_Reserve10 0 "No Alarm" 1 "Alarm Occur" ;
VAL_ 2149547842 D2P_ALARM_Reserve11 0 "No Alarm" 1 "Alarm Occur" ;
VAL_ 2149547843 D2P_ALARM_EnvExtreOverTemp 0 "No Alarm" 1 "Alarm Occur" ;
VAL_ 2149547843 D2P_ALARM_EnvOverTemp 0 "No Alarm" 1 "Alarm Occur" ;
VAL_ 2149547843 D2P_ALARM_MosOverTemp 0 "No Alarm" 1 "Alarm Occur" ;
VAL_ 2149547843 D2P_ALARM_MosExtreOverTemp 0 "No Alarm" 1 "Alarm Occur" ;
VAL_ 2149547843 D2P_ALARM_HighSideOverVolt 0 "No Alarm" 1 "Alarm Occur" ;
VAL_ 2149547843 D2P_ALARM_HighSideUnderVolt 0 "No Alarm" 1 "Alarm Occur" ;
VAL_ 2149547843 D2P_ALARM_LowSideOverVolt 0 "No Alarm" 1 "Alarm Occur" ;
VAL_ 2149547843 D2P_ALARM_HighSideOverCurr 0 "No Alarm" 1 "Alarm Occur" ;
VAL_ 2149547843 D2P_ALARM_LowSideOverCurr_HW 0 "No Alarm" 1 "Alarm Occur" ;
VAL_ 2149547843 D2P_ALARM_LowSideOverCurr_SW 0 "No Alarm" 1 "Alarm Occur" ;
VAL_ 2149547843 D2P_ALARM_SecSideOverCurr_HW 0 "No Alarm" 1 "Alarm Occur" ;
VAL_ 2149547843 D2P_ALARM_SecSideOverCurr_SW 0 "No Alarm" 1 "Alarm Occur" ;
VAL_ 2149547843 D2P_ALARM_PriSideOverCurr_HW 0 "No Alarm" 1 "Alarm Occur" ;
VAL_ 2149547843 D2P_ALARM_PriSideOverCurr_SW 0 "No Alarm" 1 "Alarm Occur" ;
VAL_ 2149547843 D2P_ALARM_LowPowerSupplyErr 0 "No Alarm" 1 "Alarm Occur" ;
VAL_ 2149547843 D2P_ALARM_MBMUComErr 0 "No Alarm" 1 "Alarm Occur" ;
VAL_ 2149547843 D2P_ALARM_DCDCMsTeSaplgErr 0 "No Alarm" 1 "Alarm Occur" ;
VAL_ 2149547843 D2P_ALARM_DCDCTeSaplgErr 0 "No Alarm" 1 "Alarm Occur" ;
VAL_ 2149547843 D2P_ALARM_VoltSamplingErr 0 "No Alarm" 1 "Alarm Occur" ;
VAL_ 2149547843 D2P_ALARM_HgSdCuSaplgErr 0 "No Alarm" 1 "Alarm Occur" ;
VAL_ 2149547843 D2P_ALARM_CtrlCurrSamplingErr 0 "No Alarm" 1 "Alarm Occur" ;
VAL_ 2149547843 D2P_ALARM_BypassFail 0 "No Alarm" 1 "Alarm Occur" ;
VAL_ 2149547843 D2P_ALARM_Reserve1 0 "No Alarm" 1 "Alarm Occur" ;
VAL_ 2149547843 D2P_ALARM_Reserve2 0 "No Alarm" 1 "Alarm Occur" ;
VAL_ 2149547843 D2P_ALARM_Reserve3 0 "No Alarm" 1 "Alarm Occur" ;
VAL_ 2149547843 D2P_ALARM_Reserve4 0 "No Alarm" 1 "Alarm Occur" ;
VAL_ 2149547843 D2P_ALARM_Reserve5 0 "No Alarm" 1 "Alarm Occur" ;
VAL_ 2149547843 D2P_ALARM_Reserve6 0 "No Alarm" 1 "Alarm Occur" ;
VAL_ 2149547843 D2P_ALARM_Reserve7 0 "No Alarm" 1 "Alarm Occur" ;
VAL_ 2149547843 D2P_ALARM_Reserve8 0 "No Alarm" 1 "Alarm Occur" ;
VAL_ 2149547843 D2P_ALARM_Reserve9 0 "No Alarm" 1 "Alarm Occur" ;
VAL_ 2149547843 D2P_ALARM_Reserve10 0 "No Alarm" 1 "Alarm Occur" ;
VAL_ 2149547843 D2P_ALARM_Reserve11 0 "No Alarm" 1 "Alarm Occur" ;
VAL_ 2149547844 D2P_ALARM_EnvExtreOverTemp 0 "No Alarm" 1 "Alarm Occur" ;
VAL_ 2149547844 D2P_ALARM_EnvOverTemp 0 "No Alarm" 1 "Alarm Occur" ;
VAL_ 2149547844 D2P_ALARM_MosOverTemp 0 "No Alarm" 1 "Alarm Occur" ;
VAL_ 2149547844 D2P_ALARM_MosExtreOverTemp 0 "No Alarm" 1 "Alarm Occur" ;
VAL_ 2149547844 D2P_ALARM_HighSideOverVolt 0 "No Alarm" 1 "Alarm Occur" ;
VAL_ 2149547844 D2P_ALARM_HighSideUnderVolt 0 "No Alarm" 1 "Alarm Occur" ;
VAL_ 2149547844 D2P_ALARM_LowSideOverVolt 0 "No Alarm" 1 "Alarm Occur" ;
VAL_ 2149547844 D2P_ALARM_HighSideOverCurr 0 "No Alarm" 1 "Alarm Occur" ;
VAL_ 2149547844 D2P_ALARM_LowSideOverCurr_HW 0 "No Alarm" 1 "Alarm Occur" ;
VAL_ 2149547844 D2P_ALARM_LowSideOverCurr_SW 0 "No Alarm" 1 "Alarm Occur" ;
VAL_ 2149547844 D2P_ALARM_SecSideOverCurr_HW 0 "No Alarm" 1 "Alarm Occur" ;
VAL_ 2149547844 D2P_ALARM_SecSideOverCurr_SW 0 "No Alarm" 1 "Alarm Occur" ;
VAL_ 2149547844 D2P_ALARM_PriSideOverCurr_HW 0 "No Alarm" 1 "Alarm Occur" ;
VAL_ 2149547844 D2P_ALARM_PriSideOverCurr_SW 0 "No Alarm" 1 "Alarm Occur" ;
VAL_ 2149547844 D2P_ALARM_LowPowerSupplyErr 0 "No Alarm" 1 "Alarm Occur" ;
VAL_ 2149547844 D2P_ALARM_MBMUComErr 0 "No Alarm" 1 "Alarm Occur" ;
VAL_ 2149547844 D2P_ALARM_DCDCMsTeSaplgErr 0 "No Alarm" 1 "Alarm Occur" ;
VAL_ 2149547844 D2P_ALARM_DCDCTeSaplgErr 0 "No Alarm" 1 "Alarm Occur" ;
VAL_ 2149547844 D2P_ALARM_VoltSamplingErr 0 "No Alarm" 1 "Alarm Occur" ;
VAL_ 2149547844 D2P_ALARM_HgSdCuSaplgErr 0 "No Alarm" 1 "Alarm Occur" ;
VAL_ 2149547844 D2P_ALARM_CtrlCurrSamplingErr 0 "No Alarm" 1 "Alarm Occur" ;
VAL_ 2149547844 D2P_ALARM_BypassFail 0 "No Alarm" 1 "Alarm Occur" ;
VAL_ 2149547844 D2P_ALARM_Reserve1 0 "No Alarm" 1 "Alarm Occur" ;
VAL_ 2149547844 D2P_ALARM_Reserve2 0 "No Alarm" 1 "Alarm Occur" ;
VAL_ 2149547844 D2P_ALARM_Reserve3 0 "No Alarm" 1 "Alarm Occur" ;
VAL_ 2149547844 D2P_ALARM_Reserve4 0 "No Alarm" 1 "Alarm Occur" ;
VAL_ 2149547844 D2P_ALARM_Reserve5 0 "No Alarm" 1 "Alarm Occur" ;
VAL_ 2149547844 D2P_ALARM_Reserve6 0 "No Alarm" 1 "Alarm Occur" ;
VAL_ 2149547844 D2P_ALARM_Reserve7 0 "No Alarm" 1 "Alarm Occur" ;
VAL_ 2149547844 D2P_ALARM_Reserve8 0 "No Alarm" 1 "Alarm Occur" ;
VAL_ 2149547844 D2P_ALARM_Reserve9 0 "No Alarm" 1 "Alarm Occur" ;
VAL_ 2149547844 D2P_ALARM_Reserve10 0 "No Alarm" 1 "Alarm Occur" ;
VAL_ 2149547844 D2P_ALARM_Reserve11 0 "No Alarm" 1 "Alarm Occur" ;
VAL_ 2149547845 D2P_ALARM_EnvExtreOverTemp 0 "No Alarm" 1 "Alarm Occur" ;
VAL_ 2149547845 D2P_ALARM_EnvOverTemp 0 "No Alarm" 1 "Alarm Occur" ;
VAL_ 2149547845 D2P_ALARM_MosOverTemp 0 "No Alarm" 1 "Alarm Occur" ;
VAL_ 2149547845 D2P_ALARM_MosExtreOverTemp 0 "No Alarm" 1 "Alarm Occur" ;
VAL_ 2149547845 D2P_ALARM_HighSideOverVolt 0 "No Alarm" 1 "Alarm Occur" ;
VAL_ 2149547845 D2P_ALARM_HighSideUnderVolt 0 "No Alarm" 1 "Alarm Occur" ;
VAL_ 2149547845 D2P_ALARM_LowSideOverVolt 0 "No Alarm" 1 "Alarm Occur" ;
VAL_ 2149547845 D2P_ALARM_HighSideOverCurr 0 "No Alarm" 1 "Alarm Occur" ;
VAL_ 2149547845 D2P_ALARM_LowSideOverCurr_HW 0 "No Alarm" 1 "Alarm Occur" ;
VAL_ 2149547845 D2P_ALARM_LowSideOverCurr_SW 0 "No Alarm" 1 "Alarm Occur" ;
VAL_ 2149547845 D2P_ALARM_SecSideOverCurr_HW 0 "No Alarm" 1 "Alarm Occur" ;
VAL_ 2149547845 D2P_ALARM_SecSideOverCurr_SW 0 "No Alarm" 1 "Alarm Occur" ;
VAL_ 2149547845 D2P_ALARM_PriSideOverCurr_HW 0 "No Alarm" 1 "Alarm Occur" ;
VAL_ 2149547845 D2P_ALARM_PriSideOverCurr_SW 0 "No Alarm" 1 "Alarm Occur" ;
VAL_ 2149547845 D2P_ALARM_LowPowerSupplyErr 0 "No Alarm" 1 "Alarm Occur" ;
VAL_ 2149547845 D2P_ALARM_MBMUComErr 0 "No Alarm" 1 "Alarm Occur" ;
VAL_ 2149547845 D2P_ALARM_DCDCMsTeSaplgErr 0 "No Alarm" 1 "Alarm Occur" ;
VAL_ 2149547845 D2P_ALARM_DCDCTeSaplgErr 0 "No Alarm" 1 "Alarm Occur" ;
VAL_ 2149547845 D2P_ALARM_VoltSamplingErr 0 "No Alarm" 1 "Alarm Occur" ;
VAL_ 2149547845 D2P_ALARM_HgSdCuSaplgErr 0 "No Alarm" 1 "Alarm Occur" ;
VAL_ 2149547845 D2P_ALARM_CtrlCurrSamplingErr 0 "No Alarm" 1 "Alarm Occur" ;
VAL_ 2149547845 D2P_ALARM_BypassFail 0 "No Alarm" 1 "Alarm Occur" ;
VAL_ 2149547845 D2P_ALARM_Reserve1 0 "No Alarm" 1 "Alarm Occur" ;
VAL_ 2149547845 D2P_ALARM_Reserve2 0 "No Alarm" 1 "Alarm Occur" ;
VAL_ 2149547845 D2P_ALARM_Reserve3 0 "No Alarm" 1 "Alarm Occur" ;
VAL_ 2149547845 D2P_ALARM_Reserve4 0 "No Alarm" 1 "Alarm Occur" ;
VAL_ 2149547845 D2P_ALARM_Reserve5 0 "No Alarm" 1 "Alarm Occur" ;
VAL_ 2149547845 D2P_ALARM_Reserve6 0 "No Alarm" 1 "Alarm Occur" ;
VAL_ 2149547845 D2P_ALARM_Reserve7 0 "No Alarm" 1 "Alarm Occur" ;
VAL_ 2149547845 D2P_ALARM_Reserve8 0 "No Alarm" 1 "Alarm Occur" ;
VAL_ 2149547845 D2P_ALARM_Reserve9 0 "No Alarm" 1 "Alarm Occur" ;
VAL_ 2149547845 D2P_ALARM_Reserve10 0 "No Alarm" 1 "Alarm Occur" ;
VAL_ 2149547845 D2P_ALARM_Reserve11 0 "No Alarm" 1 "Alarm Occur" ;
VAL_ 2149547846 D2P_ALARM_EnvExtreOverTemp 0 "No Alarm" 1 "Alarm Occur" ;
VAL_ 2149547846 D2P_ALARM_EnvOverTemp 0 "No Alarm" 1 "Alarm Occur" ;
VAL_ 2149547846 D2P_ALARM_MosOverTemp 0 "No Alarm" 1 "Alarm Occur" ;
VAL_ 2149547846 D2P_ALARM_MosExtreOverTemp 0 "No Alarm" 1 "Alarm Occur" ;
VAL_ 2149547846 D2P_ALARM_HighSideOverVolt 0 "No Alarm" 1 "Alarm Occur" ;
VAL_ 2149547846 D2P_ALARM_HighSideUnderVolt 0 "No Alarm" 1 "Alarm Occur" ;
VAL_ 2149547846 D2P_ALARM_LowSideOverVolt 0 "No Alarm" 1 "Alarm Occur" ;
VAL_ 2149547846 D2P_ALARM_HighSideOverCurr 0 "No Alarm" 1 "Alarm Occur" ;
VAL_ 2149547846 D2P_ALARM_LowSideOverCurr_HW 0 "No Alarm" 1 "Alarm Occur" ;
VAL_ 2149547846 D2P_ALARM_LowSideOverCurr_SW 0 "No Alarm" 1 "Alarm Occur" ;
VAL_ 2149547846 D2P_ALARM_SecSideOverCurr_HW 0 "No Alarm" 1 "Alarm Occur" ;
VAL_ 2149547846 D2P_ALARM_SecSideOverCurr_SW 0 "No Alarm" 1 "Alarm Occur" ;
VAL_ 2149547846 D2P_ALARM_PriSideOverCurr_HW 0 "No Alarm" 1 "Alarm Occur" ;
VAL_ 2149547846 D2P_ALARM_PriSideOverCurr_SW 0 "No Alarm" 1 "Alarm Occur" ;
VAL_ 2149547846 D2P_ALARM_LowPowerSupplyErr 0 "No Alarm" 1 "Alarm Occur" ;
VAL_ 2149547846 D2P_ALARM_MBMUComErr 0 "No Alarm" 1 "Alarm Occur" ;
VAL_ 2149547846 D2P_ALARM_DCDCMsTeSaplgErr 0 "No Alarm" 1 "Alarm Occur" ;
VAL_ 2149547846 D2P_ALARM_DCDCTeSaplgErr 0 "No Alarm" 1 "Alarm Occur" ;
VAL_ 2149547846 D2P_ALARM_VoltSamplingErr 0 "No Alarm" 1 "Alarm Occur" ;
VAL_ 2149547846 D2P_ALARM_HgSdCuSaplgErr 0 "No Alarm" 1 "Alarm Occur" ;
VAL_ 2149547846 D2P_ALARM_CtrlCurrSamplingErr 0 "No Alarm" 1 "Alarm Occur" ;
VAL_ 2149547846 D2P_ALARM_BypassFail 0 "No Alarm" 1 "Alarm Occur" ;
VAL_ 2149547846 D2P_ALARM_Reserve1 0 "No Alarm" 1 "Alarm Occur" ;
VAL_ 2149547846 D2P_ALARM_Reserve2 0 "No Alarm" 1 "Alarm Occur" ;
VAL_ 2149547846 D2P_ALARM_Reserve3 0 "No Alarm" 1 "Alarm Occur" ;
VAL_ 2149547846 D2P_ALARM_Reserve4 0 "No Alarm" 1 "Alarm Occur" ;
VAL_ 2149547846 D2P_ALARM_Reserve5 0 "No Alarm" 1 "Alarm Occur" ;
VAL_ 2149547846 D2P_ALARM_Reserve6 0 "No Alarm" 1 "Alarm Occur" ;
VAL_ 2149547846 D2P_ALARM_Reserve7 0 "No Alarm" 1 "Alarm Occur" ;
VAL_ 2149547846 D2P_ALARM_Reserve8 0 "No Alarm" 1 "Alarm Occur" ;
VAL_ 2149547846 D2P_ALARM_Reserve9 0 "No Alarm" 1 "Alarm Occur" ;
VAL_ 2149547846 D2P_ALARM_Reserve10 0 "No Alarm" 1 "Alarm Occur" ;
VAL_ 2149547846 D2P_ALARM_Reserve11 0 "No Alarm" 1 "Alarm Occur" ;
VAL_ 2149547847 D2P_ALARM_EnvExtreOverTemp 0 "No Alarm" 1 "Alarm Occur" ;
VAL_ 2149547847 D2P_ALARM_EnvOverTemp 0 "No Alarm" 1 "Alarm Occur" ;
VAL_ 2149547847 D2P_ALARM_MosOverTemp 0 "No Alarm" 1 "Alarm Occur" ;
VAL_ 2149547847 D2P_ALARM_MosExtreOverTemp 0 "No Alarm" 1 "Alarm Occur" ;
VAL_ 2149547847 D2P_ALARM_HighSideOverVolt 0 "No Alarm" 1 "Alarm Occur" ;
VAL_ 2149547847 D2P_ALARM_HighSideUnderVolt 0 "No Alarm" 1 "Alarm Occur" ;
VAL_ 2149547847 D2P_ALARM_LowSideOverVolt 0 "No Alarm" 1 "Alarm Occur" ;
VAL_ 2149547847 D2P_ALARM_HighSideOverCurr 0 "No Alarm" 1 "Alarm Occur" ;
VAL_ 2149547847 D2P_ALARM_LowSideOverCurr_HW 0 "No Alarm" 1 "Alarm Occur" ;
VAL_ 2149547847 D2P_ALARM_LowSideOverCurr_SW 0 "No Alarm" 1 "Alarm Occur" ;
VAL_ 2149547847 D2P_ALARM_SecSideOverCurr_HW 0 "No Alarm" 1 "Alarm Occur" ;
VAL_ 2149547847 D2P_ALARM_SecSideOverCurr_SW 0 "No Alarm" 1 "Alarm Occur" ;
VAL_ 2149547847 D2P_ALARM_PriSideOverCurr_HW 0 "No Alarm" 1 "Alarm Occur" ;
VAL_ 2149547847 D2P_ALARM_PriSideOverCurr_SW 0 "No Alarm" 1 "Alarm Occur" ;
VAL_ 2149547847 D2P_ALARM_LowPowerSupplyErr 0 "No Alarm" 1 "Alarm Occur" ;
VAL_ 2149547847 D2P_ALARM_MBMUComErr 0 "No Alarm" 1 "Alarm Occur" ;
VAL_ 2149547847 D2P_ALARM_DCDCMsTeSaplgErr 0 "No Alarm" 1 "Alarm Occur" ;
VAL_ 2149547847 D2P_ALARM_DCDCTeSaplgErr 0 "No Alarm" 1 "Alarm Occur" ;
VAL_ 2149547847 D2P_ALARM_VoltSamplingErr 0 "No Alarm" 1 "Alarm Occur" ;
VAL_ 2149547847 D2P_ALARM_HgSdCuSaplgErr 0 "No Alarm" 1 "Alarm Occur" ;
VAL_ 2149547847 D2P_ALARM_CtrlCurrSamplingErr 0 "No Alarm" 1 "Alarm Occur" ;
VAL_ 2149547847 D2P_ALARM_BypassFail 0 "No Alarm" 1 "Alarm Occur" ;
VAL_ 2149547847 D2P_ALARM_Reserve1 0 "No Alarm" 1 "Alarm Occur" ;
VAL_ 2149547847 D2P_ALARM_Reserve2 0 "No Alarm" 1 "Alarm Occur" ;
VAL_ 2149547847 D2P_ALARM_Reserve3 0 "No Alarm" 1 "Alarm Occur" ;
VAL_ 2149547847 D2P_ALARM_Reserve4 0 "No Alarm" 1 "Alarm Occur" ;
VAL_ 2149547847 D2P_ALARM_Reserve5 0 "No Alarm" 1 "Alarm Occur" ;
VAL_ 2149547847 D2P_ALARM_Reserve6 0 "No Alarm" 1 "Alarm Occur" ;
VAL_ 2149547847 D2P_ALARM_Reserve7 0 "No Alarm" 1 "Alarm Occur" ;
VAL_ 2149547847 D2P_ALARM_Reserve8 0 "No Alarm" 1 "Alarm Occur" ;
VAL_ 2149547847 D2P_ALARM_Reserve9 0 "No Alarm" 1 "Alarm Occur" ;
VAL_ 2149547847 D2P_ALARM_Reserve10 0 "No Alarm" 1 "Alarm Occur" ;
VAL_ 2149547847 D2P_ALARM_Reserve11 0 "No Alarm" 1 "Alarm Occur" ;
VERSION ""

NS_ :

BS_:

BU_: MBMU PC SBMU IMM ETH DCDC LEMS

BO_ 2149547879 D2P_ALARM__39: 8 DCDC
 SG_ D2P_ALARM_EnvExtreOverTemp : 0|1@1+ (1,0) [0|1] ""  PC
 SG_ D2P_ALARM_EnvOverTemp : 1|1@1+ (1,0) [0|1] ""  PC
 SG_ D2P_ALARM_MosOverTemp : 2|1@1+ (1,0) [0|1] ""  PC
 SG_ D2P_ALARM_MosExtreOverTemp : 3|1@1+ (1,0) [0|1] ""  PC
 SG_ D2P_ALARM_HighSideOverVolt : 4|1@1+ (1,0) [0|1] ""  PC
 SG_ D2P_ALARM_HighSideUnderVolt : 5|1@1+ (1,0) [0|1] ""  PC
 SG_ D2P_ALARM_LowSideOverVolt : 6|1@1+ (1,0) [0|1] ""  PC
 SG_ D2P_ALARM_HighSideOverCurr : 7|1@1+ (1,0) [0|1] ""  PC
 SG_ D2P_ALARM_LowSideOverCurr_HW : 8|1@1+ (1,0) [0|1] ""  PC
 SG_ D2P_ALARM_LowSideOverCurr_SW : 9|1@1+ (1,0) [0|1] ""  PC
 SG_ D2P_ALARM_SecSideOverCurr_HW : 10|1@1+ (1,0) [0|1] ""  PC
 SG_ D2P_ALARM_SecSideOverCurr_SW : 11|1@1+ (1,0) [0|1] ""  PC
 SG_ D2P_ALARM_PriSideOverCurr_HW : 12|1@1+ (1,0) [0|1] ""  PC
 SG_ D2P_ALARM_PriSideOverCurr_SW : 13|1@1+ (1,0) [0|1] ""  PC
 SG_ D2P_ALARM_LowPowerSupplyErr : 14|1@1+ (1,0) [0|1] ""  PC
 SG_ D2P_ALARM_MBMUComErr : 15|1@1+ (1,0) [0|1] ""  PC
 SG_ D2P_ALARM_DCDCMsTeSaplgErr : 16|1@1+ (1,0) [0|1] ""  PC
 SG_ D2P_ALARM_DCDCTeSaplgErr : 17|1@1+ (1,0) [0|1] ""  PC
 SG_ D2P_ALARM_VoltSamplingErr : 18|1@1+ (1,0) [0|1] ""  PC
 SG_ D2P_ALARM_HgSdCuSaplgErr : 19|1@1+ (1,0) [0|1] ""  PC
 SG_ D2P_ALARM_CtrlCurrSamplingErr : 20|1@1+ (1,0) [0|1] ""  PC
 SG_ D2P_ALARM_BypassFail : 21|1@1+ (1,0) [0|1] ""  PC
 SG_ D2P_ALARM_Reserve1 : 22|1@1+ (1,0) [0|1] ""  PC
 SG_ D2P_ALARM_Reserve2 : 23|1@1+ (1,0) [0|1] ""  PC
 SG_ D2P_ALARM_Reserve3 : 24|1@1+ (1,0) [0|1] ""  PC
 SG_ D2P_ALARM_Reserve4 : 25|1@1+ (1,0) [0|1] ""  PC
 SG_ D2P_ALARM_Reserve5 : 26|1@1+ (1,0) [0|1] ""  PC
 SG_ D2P_ALARM_Reserve6 : 27|1@1+ (1,0) [0|1] ""  PC
 SG_ D2P_ALARM_Reserve7 : 28|1@1+ (1,0) [0|1] ""  PC
 SG_ D2P_ALARM_Reserve8 : 29|1@1+ (1,0) [0|1] ""  PC
 SG_ D2P_ALARM_Reserve9 : 30|1@1+ (1,0) [0|1] ""  PC
 SG_ D2P_ALARM_Reserve10 : 31|1@1+ (1,0) [0|1] ""  PC
 SG_ D2P_ALARM_Reserve11 : 32|32@1+ (1,0) [0|4294967295] ""  PC

BO_ 2149547880 D2P_ALARM__40: 8 DCDC
 SG_ D2P_ALARM_EnvExtreOverTemp : 0|1@1+ (1,0) [0|1] ""  PC
 SG_ D2P_ALARM_EnvOverTemp : 1|1@1+ (1,0) [0|1] ""  PC
 SG_ D2P_ALARM_MosOverTemp : 2|1@1+ (1,0) [0|1] ""  PC
 SG_ D2P_ALARM_MosExtreOverTemp : 3|1@1+ (1,0) [0|1] ""  PC
 SG_ D2P_ALARM_HighSideOverVolt : 4|1@1+ (1,0) [0|1] ""  PC
 SG_ D2P_ALARM_HighSideUnderVolt : 5|1@1+ (1,0) [0|1] ""  PC
 SG_ D2P_ALARM_LowSideOverVolt : 6|1@1+ (1,0) [0|1] ""  PC
 SG_ D2P_ALARM_HighSideOverCurr : 7|1@1+ (1,0) [0|1] ""  PC
 SG_ D2P_ALARM_LowSideOverCurr_HW : 8|1@1+ (1,0) [0|1] ""  PC
 SG_ D2P_ALARM_LowSideOverCurr_SW : 9|1@1+ (1,0) [0|1] ""  PC
 SG_ D2P_ALARM_SecSideOverCurr_HW : 10|1@1+ (1,0) [0|1] ""  PC
 SG_ D2P_ALARM_SecSideOverCurr_SW : 11|1@1+ (1,0) [0|1] ""  PC
 SG_ D2P_ALARM_PriSideOverCurr_HW : 12|1@1+ (1,0) [0|1] ""  PC
 SG_ D2P_ALARM_PriSideOverCurr_SW : 13|1@1+ (1,0) [0|1] ""  PC
 SG_ D2P_ALARM_LowPowerSupplyErr : 14|1@1+ (1,0) [0|1] ""  PC
 SG_ D2P_ALARM_MBMUComErr : 15|1@1+ (1,0) [0|1] ""  PC
 SG_ D2P_ALARM_DCDCMsTeSaplgErr : 16|1@1+ (1,0) [0|1] ""  PC
 SG_ D2P_ALARM_DCDCTeSaplgErr : 17|1@1+ (1,0) [0|1] ""  PC
 SG_ D2P_ALARM_VoltSamplingErr : 18|1@1+ (1,0) [0|1] ""  PC
 SG_ D2P_ALARM_HgSdCuSaplgErr : 19|1@1+ (1,0) [0|1] ""  PC
 SG_ D2P_ALARM_CtrlCurrSamplingErr : 20|1@1+ (1,0) [0|1] ""  PC
 SG_ D2P_ALARM_BypassFail : 21|1@1+ (1,0) [0|1] ""  PC
 SG_ D2P_ALARM_Reserve1 : 22|1@1+ (1,0) [0|1] ""  PC
 SG_ D2P_ALARM_Reserve2 : 23|1@1+ (1,0) [0|1] ""  PC
 SG_ D2P_ALARM_Reserve3 : 24|1@1+ (1,0) [0|1] ""  PC
 SG_ D2P_ALARM_Reserve4 : 25|1@1+ (1,0) [0|1] ""  PC
 SG_ D2P_ALARM_Reserve5 : 26|1@1+ (1,0) [0|1] ""  PC
 SG_ D2P_ALARM_Reserve6 : 27|1@1+ (1,0) [0|1] ""  PC
 SG_ D2P_ALARM_Reserve7 : 28|1@1+ (1,0) [0|1] ""  PC
 SG_ D2P_ALARM_Reserve8 : 29|1@1+ (1,0) [0|1] ""  PC
 SG_ D2P_ALARM_Reserve9 : 30|1@1+ (1,0) [0|1] ""  PC
 SG_ D2P_ALARM_Reserve10 : 31|1@1+ (1,0) [0|1] ""  PC
 SG_ D2P_ALARM_Reserve11 : 32|32@1+ (1,0) [0|4294967295] ""  PC

BO_ 2149547881 D2P_ALARM__41: 8 DCDC
 SG_ D2P_ALARM_EnvExtreOverTemp : 0|1@1+ (1,0) [0|1] ""  PC
 SG_ D2P_ALARM_EnvOverTemp : 1|1@1+ (1,0) [0|1] ""  PC
 SG_ D2P_ALARM_MosOverTemp : 2|1@1+ (1,0) [0|1] ""  PC
 SG_ D2P_ALARM_MosExtreOverTemp : 3|1@1+ (1,0) [0|1] ""  PC
 SG_ D2P_ALARM_HighSideOverVolt : 4|1@1+ (1,0) [0|1] ""  PC
 SG_ D2P_ALARM_HighSideUnderVolt : 5|1@1+ (1,0) [0|1] ""  PC
 SG_ D2P_ALARM_LowSideOverVolt : 6|1@1+ (1,0) [0|1] ""  PC
 SG_ D2P_ALARM_HighSideOverCurr : 7|1@1+ (1,0) [0|1] ""  PC
 SG_ D2P_ALARM_LowSideOverCurr_HW : 8|1@1+ (1,0) [0|1] ""  PC
 SG_ D2P_ALARM_LowSideOverCurr_SW : 9|1@1+ (1,0) [0|1] ""  PC
 SG_ D2P_ALARM_SecSideOverCurr_HW : 10|1@1+ (1,0) [0|1] ""  PC
 SG_ D2P_ALARM_SecSideOverCurr_SW : 11|1@1+ (1,0) [0|1] ""  PC
 SG_ D2P_ALARM_PriSideOverCurr_HW : 12|1@1+ (1,0) [0|1] ""  PC
 SG_ D2P_ALARM_PriSideOverCurr_SW : 13|1@1+ (1,0) [0|1] ""  PC
 SG_ D2P_ALARM_LowPowerSupplyErr : 14|1@1+ (1,0) [0|1] ""  PC
 SG_ D2P_ALARM_MBMUComErr : 15|1@1+ (1,0) [0|1] ""  PC
 SG_ D2P_ALARM_DCDCMsTeSaplgErr : 16|1@1+ (1,0) [0|1] ""  PC
 SG_ D2P_ALARM_DCDCTeSaplgErr : 17|1@1+ (1,0) [0|1] ""  PC
 SG_ D2P_ALARM_VoltSamplingErr : 18|1@1+ (1,0) [0|1] ""  PC
 SG_ D2P_ALARM_HgSdCuSaplgErr : 19|1@1+ (1,0) [0|1] ""  PC
 SG_ D2P_ALARM_CtrlCurrSamplingErr : 20|1@1+ (1,0) [0|1] ""  PC
 SG_ D2P_ALARM_BypassFail : 21|1@1+ (1,0) [0|1] ""  PC
 SG_ D2P_ALARM_Reserve1 : 22|1@1+ (1,0) [0|1] ""  PC
 SG_ D2P_ALARM_Reserve2 : 23|1@1+ (1,0) [0|1] ""  PC
 SG_ D2P_ALARM_Reserve3 : 24|1@1+ (1,0) [0|1] ""  PC
 SG_ D2P_ALARM_Reserve4 : 25|1@1+ (1,0) [0|1] ""  PC
 SG_ D2P_ALARM_Reserve5 : 26|1@1+ (1,0) [0|1] ""  PC
 SG_ D2P_ALARM_Reserve6 : 27|1@1+ (1,0) [0|1] ""  PC
 SG_ D2P_ALARM_Reserve7 : 28|1@1+ (1,0) [0|1] ""  PC
 SG_ D2P_ALARM_Reserve8 : 29|1@1+ (1,0) [0|1] ""  PC
 SG_ D2P_ALARM_Reserve9 : 30|1@1+ (1,0) [0|1] ""  PC
 SG_ D2P_ALARM_Reserve10 : 31|1@1+ (1,0) [0|1] ""  PC
 SG_ D2P_ALARM_Reserve11 : 32|32@1+ (1,0) [0|4294967295] ""  PC

BO_ 2149547882 D2P_ALARM__42: 8 DCDC
 SG_ D2P_ALARM_EnvExtreOverTemp : 0|1@1+ (1,0) [0|1] ""  PC
 SG_ D2P_ALARM_EnvOverTemp : 1|1@1+ (1,0) [0|1] ""  PC
 SG_ D2P_ALARM_MosOverTemp : 2|1@1+ (1,0) [0|1] ""  PC
 SG_ D2P_ALARM_MosExtreOverTemp : 3|1@1+ (1,0) [0|1] ""  PC
 SG_ D2P_ALARM_HighSideOverVolt : 4|1@1+ (1,0) [0|1] ""  PC
 SG_ D2P_ALARM_HighSideUnderVolt : 5|1@1+ (1,0) [0|1] ""  PC
 SG_ D2P_ALARM_LowSideOverVolt : 6|1@1+ (1,0) [0|1] ""  PC
 SG_ D2P_ALARM_HighSideOverCurr : 7|1@1+ (1,0) [0|1] ""  PC
 SG_ D2P_ALARM_LowSideOverCurr_HW : 8|1@1+ (1,0) [0|1] ""  PC
 SG_ D2P_ALARM_LowSideOverCurr_SW : 9|1@1+ (1,0) [0|1] ""  PC
 SG_ D2P_ALARM_SecSideOverCurr_HW : 10|1@1+ (1,0) [0|1] ""  PC
 SG_ D2P_ALARM_SecSideOverCurr_SW : 11|1@1+ (1,0) [0|1] ""  PC
 SG_ D2P_ALARM_PriSideOverCurr_HW : 12|1@1+ (1,0) [0|1] ""  PC
 SG_ D2P_ALARM_PriSideOverCurr_SW : 13|1@1+ (1,0) [0|1] ""  PC
 SG_ D2P_ALARM_LowPowerSupplyErr : 14|1@1+ (1,0) [0|1] ""  PC
 SG_ D2P_ALARM_MBMUComErr : 15|1@1+ (1,0) [0|1] ""  PC
 SG_ D2P_ALARM_DCDCMsTeSaplgErr : 16|1@1+ (1,0) [0|1] ""  PC
 SG_ D2P_ALARM_DCDCTeSaplgErr : 17|1@1+ (1,0) [0|1] ""  PC
 SG_ D2P_ALARM_VoltSamplingErr : 18|1@1+ (1,0) [0|1] ""  PC
 SG_ D2P_ALARM_HgSdCuSaplgErr : 19|1@1+ (1,0) [0|1] ""  PC
 SG_ D2P_ALARM_CtrlCurrSamplingErr : 20|1@1+ (1,0) [0|1] ""  PC
 SG_ D2P_ALARM_BypassFail : 21|1@1+ (1,0) [0|1] ""  PC
 SG_ D2P_ALARM_Reserve1 : 22|1@1+ (1,0) [0|1] ""  PC
 SG_ D2P_ALARM_Reserve2 : 23|1@1+ (1,0) [0|1] ""  PC
 SG_ D2P_ALARM_Reserve3 : 24|1@1+ (1,0) [0|1] ""  PC
 SG_ D2P_ALARM_Reserve4 : 25|1@1+ (1,0) [0|1] ""  PC
 SG_ D2P_ALARM_Reserve5 : 26|1@1+ (1,0) [0|1] ""  PC
 SG_ D2P_ALARM_Reserve6 : 27|1@1+ (1,0) [0|1] ""  PC
 SG_ D2P_ALARM_Reserve7 : 28|1@1+ (1,0) [0|1] ""  PC
 SG_ D2P_ALARM_Reserve8 : 29|1@1+ (1,0) [0|1] ""  PC
 SG_ D2P_ALARM_Reserve9 : 30|1@1+ (1,0) [0|1] ""  PC
 SG_ D2P_ALARM_Reserve10 : 31|1@1+ (1,0) [0|1] ""  PC
 SG_ D2P_ALARM_Reserve11 : 32|32@1+ (1,0) [0|4294967295] ""  PC

BO_ 2149547883 D2P_ALARM__43: 8 DCDC
 SG_ D2P_ALARM_EnvExtreOverTemp : 0|1@1+ (1,0) [0|1] ""  PC
 SG_ D2P_ALARM_EnvOverTemp : 1|1@1+ (1,0) [0|1] ""  PC
 SG_ D2P_ALARM_MosOverTemp : 2|1@1+ (1,0) [0|1] ""  PC
 SG_ D2P_ALARM_MosExtreOverTemp : 3|1@1+ (1,0) [0|1] ""  PC
 SG_ D2P_ALARM_HighSideOverVolt : 4|1@1+ (1,0) [0|1] ""  PC
 SG_ D2P_ALARM_HighSideUnderVolt : 5|1@1+ (1,0) [0|1] ""  PC
 SG_ D2P_ALARM_LowSideOverVolt : 6|1@1+ (1,0) [0|1] ""  PC
 SG_ D2P_ALARM_HighSideOverCurr : 7|1@1+ (1,0) [0|1] ""  PC
 SG_ D2P_ALARM_LowSideOverCurr_HW : 8|1@1+ (1,0) [0|1] ""  PC
 SG_ D2P_ALARM_LowSideOverCurr_SW : 9|1@1+ (1,0) [0|1] ""  PC
 SG_ D2P_ALARM_SecSideOverCurr_HW : 10|1@1+ (1,0) [0|1] ""  PC
 SG_ D2P_ALARM_SecSideOverCurr_SW : 11|1@1+ (1,0) [0|1] ""  PC
 SG_ D2P_ALARM_PriSideOverCurr_HW : 12|1@1+ (1,0) [0|1] ""  PC
 SG_ D2P_ALARM_PriSideOverCurr_SW : 13|1@1+ (1,0) [0|1] ""  PC
 SG_ D2P_ALARM_LowPowerSupplyErr : 14|1@1+ (1,0) [0|1] ""  PC
 SG_ D2P_ALARM_MBMUComErr : 15|1@1+ (1,0) [0|1] ""  PC
 SG_ D2P_ALARM_DCDCMsTeSaplgErr : 16|1@1+ (1,0) [0|1] ""  PC
 SG_ D2P_ALARM_DCDCTeSaplgErr : 17|1@1+ (1,0) [0|1] ""  PC
 SG_ D2P_ALARM_VoltSamplingErr : 18|1@1+ (1,0) [0|1] ""  PC
 SG_ D2P_ALARM_HgSdCuSaplgErr : 19|1@1+ (1,0) [0|1] ""  PC
 SG_ D2P_ALARM_CtrlCurrSamplingErr : 20|1@1+ (1,0) [0|1] ""  PC
 SG_ D2P_ALARM_BypassFail : 21|1@1+ (1,0) [0|1] ""  PC
 SG_ D2P_ALARM_Reserve1 : 22|1@1+ (1,0) [0|1] ""  PC
 SG_ D2P_ALARM_Reserve2 : 23|1@1+ (1,0) [0|1] ""  PC
 SG_ D2P_ALARM_Reserve3 : 24|1@1+ (1,0) [0|1] ""  PC
 SG_ D2P_ALARM_Reserve4 : 25|1@1+ (1,0) [0|1] ""  PC
 SG_ D2P_ALARM_Reserve5 : 26|1@1+ (1,0) [0|1] ""  PC
 SG_ D2P_ALARM_Reserve6 : 27|1@1+ (1,0) [0|1] ""  PC
 SG_ D2P_ALARM_Reserve7 : 28|1@1+ (1,0) [0|1] ""  PC
 SG_ D2P_ALARM_Reserve8 : 29|1@1+ (1,0) [0|1] ""  PC
 SG_ D2P_ALARM_Reserve9 : 30|1@1+ (1,0) [0|1] ""  PC
 SG_ D2P_ALARM_Reserve10 : 31|1@1+ (1,0) [0|1] ""  PC
 SG_ D2P_ALARM_Reserve11 : 32|32@1+ (1,0) [0|4294967295] ""  PC

BO_ 2149547884 D2P_ALARM__44: 8 DCDC
 SG_ D2P_ALARM_EnvExtreOverTemp : 0|1@1+ (1,0) [0|1] ""  PC
 SG_ D2P_ALARM_EnvOverTemp : 1|1@1+ (1,0) [0|1] ""  PC
 SG_ D2P_ALARM_MosOverTemp : 2|1@1+ (1,0) [0|1] ""  PC
 SG_ D2P_ALARM_MosExtreOverTemp : 3|1@1+ (1,0) [0|1] ""  PC
 SG_ D2P_ALARM_HighSideOverVolt : 4|1@1+ (1,0) [0|1] ""  PC
 SG_ D2P_ALARM_HighSideUnderVolt : 5|1@1+ (1,0) [0|1] ""  PC
 SG_ D2P_ALARM_LowSideOverVolt : 6|1@1+ (1,0) [0|1] ""  PC
 SG_ D2P_ALARM_HighSideOverCurr : 7|1@1+ (1,0) [0|1] ""  PC
 SG_ D2P_ALARM_LowSideOverCurr_HW : 8|1@1+ (1,0) [0|1] ""  PC
 SG_ D2P_ALARM_LowSideOverCurr_SW : 9|1@1+ (1,0) [0|1] ""  PC
 SG_ D2P_ALARM_SecSideOverCurr_HW : 10|1@1+ (1,0) [0|1] ""  PC
 SG_ D2P_ALARM_SecSideOverCurr_SW : 11|1@1+ (1,0) [0|1] ""  PC
 SG_ D2P_ALARM_PriSideOverCurr_HW : 12|1@1+ (1,0) [0|1] ""  PC
 SG_ D2P_ALARM_PriSideOverCurr_SW : 13|1@1+ (1,0) [0|1] ""  PC
 SG_ D2P_ALARM_LowPowerSupplyErr : 14|1@1+ (1,0) [0|1] ""  PC
 SG_ D2P_ALARM_MBMUComErr : 15|1@1+ (1,0) [0|1] ""  PC
 SG_ D2P_ALARM_DCDCMsTeSaplgErr : 16|1@1+ (1,0) [0|1] ""  PC
 SG_ D2P_ALARM_DCDCTeSaplgErr : 17|1@1+ (1,0) [0|1] ""  PC
 SG_ D2P_ALARM_VoltSamplingErr : 18|1@1+ (1,0) [0|1] ""  PC
 SG_ D2P_ALARM_HgSdCuSaplgErr : 19|1@1+ (1,0) [0|1] ""  PC
 SG_ D2P_ALARM_CtrlCurrSamplingErr : 20|1@1+ (1,0) [0|1] ""  PC
 SG_ D2P_ALARM_BypassFail : 21|1@1+ (1,0) [0|1] ""  PC
 SG_ D2P_ALARM_Reserve1 : 22|1@1+ (1,0) [0|1] ""  PC
 SG_ D2P_ALARM_Reserve2 : 23|1@1+ (1,0) [0|1] ""  PC
 SG_ D2P_ALARM_Reserve3 : 24|1@1+ (1,0) [0|1] ""  PC
 SG_ D2P_ALARM_Reserve4 : 25|1@1+ (1,0) [0|1] ""  PC
 SG_ D2P_ALARM_Reserve5 : 26|1@1+ (1,0) [0|1] ""  PC
 SG_ D2P_ALARM_Reserve6 : 27|1@1+ (1,0) [0|1] ""  PC
 SG_ D2P_ALARM_Reserve7 : 28|1@1+ (1,0) [0|1] ""  PC
 SG_ D2P_ALARM_Reserve8 : 29|1@1+ (1,0) [0|1] ""  PC
 SG_ D2P_ALARM_Reserve9 : 30|1@1+ (1,0) [0|1] ""  PC
 SG_ D2P_ALARM_Reserve10 : 31|1@1+ (1,0) [0|1] ""  PC
 SG_ D2P_ALARM_Reserve11 : 32|32@1+ (1,0) [0|4294967295] ""  PC

BO_ 2149547885 D2P_ALARM__45: 8 DCDC
 SG_ D2P_ALARM_EnvExtreOverTemp : 0|1@1+ (1,0) [0|1] ""  PC
 SG_ D2P_ALARM_EnvOverTemp : 1|1@1+ (1,0) [0|1] ""  PC
 SG_ D2P_ALARM_MosOverTemp : 2|1@1+ (1,0) [0|1] ""  PC
 SG_ D2P_ALARM_MosExtreOverTemp : 3|1@1+ (1,0) [0|1] ""  PC
 SG_ D2P_ALARM_HighSideOverVolt : 4|1@1+ (1,0) [0|1] ""  PC
 SG_ D2P_ALARM_HighSideUnderVolt : 5|1@1+ (1,0) [0|1] ""  PC
 SG_ D2P_ALARM_LowSideOverVolt : 6|1@1+ (1,0) [0|1] ""  PC
 SG_ D2P_ALARM_HighSideOverCurr : 7|1@1+ (1,0) [0|1] ""  PC
 SG_ D2P_ALARM_LowSideOverCurr_HW : 8|1@1+ (1,0) [0|1] ""  PC
 SG_ D2P_ALARM_LowSideOverCurr_SW : 9|1@1+ (1,0) [0|1] ""  PC
 SG_ D2P_ALARM_SecSideOverCurr_HW : 10|1@1+ (1,0) [0|1] ""  PC
 SG_ D2P_ALARM_SecSideOverCurr_SW : 11|1@1+ (1,0) [0|1] ""  PC
 SG_ D2P_ALARM_PriSideOverCurr_HW : 12|1@1+ (1,0) [0|1] ""  PC
 SG_ D2P_ALARM_PriSideOverCurr_SW : 13|1@1+ (1,0) [0|1] ""  PC
 SG_ D2P_ALARM_LowPowerSupplyErr : 14|1@1+ (1,0) [0|1] ""  PC
 SG_ D2P_ALARM_MBMUComErr : 15|1@1+ (1,0) [0|1] ""  PC
 SG_ D2P_ALARM_DCDCMsTeSaplgErr : 16|1@1+ (1,0) [0|1] ""  PC
 SG_ D2P_ALARM_DCDCTeSaplgErr : 17|1@1+ (1,0) [0|1] ""  PC
 SG_ D2P_ALARM_VoltSamplingErr : 18|1@1+ (1,0) [0|1] ""  PC
 SG_ D2P_ALARM_HgSdCuSaplgErr : 19|1@1+ (1,0) [0|1] ""  PC
 SG_ D2P_ALARM_CtrlCurrSamplingErr : 20|1@1+ (1,0) [0|1] ""  PC
 SG_ D2P_ALARM_BypassFail : 21|1@1+ (1,0) [0|1] ""  PC
 SG_ D2P_ALARM_Reserve1 : 22|1@1+ (1,0) [0|1] ""  PC
 SG_ D2P_ALARM_Reserve2 : 23|1@1+ (1,0) [0|1] ""  PC
 SG_ D2P_ALARM_Reserve3 : 24|1@1+ (1,0) [0|1] ""  PC
 SG_ D2P_ALARM_Reserve4 : 25|1@1+ (1,0) [0|1] ""  PC
 SG_ D2P_ALARM_Reserve5 : 26|1@1+ (1,0) [0|1] ""  PC
 SG_ D2P_ALARM_Reserve6 : 27|1@1+ (1,0) [0|1] ""  PC
 SG_ D2P_ALARM_Reserve7 : 28|1@1+ (1,0) [0|1] ""  PC
 SG_ D2P_ALARM_Reserve8 : 29|1@1+ (1,0) [0|1] ""  PC
 SG_ D2P_ALARM_Reserve9 : 30|1@1+ (1,0) [0|1] ""  PC
 SG_ D2P_ALARM_Reserve10 : 31|1@1+ (1,0) [0|1] ""  PC
 SG_ D2P_ALARM_Reserve11 : 32|32@1+ (1,0) [0|4294967295] ""  PC

BO_ 2149547886 D2P_ALARM__46: 8 DCDC
 SG_ D2P_ALARM_EnvExtreOverTemp : 0|1@1+ (1,0) [0|1] ""  PC
 SG_ D2P_ALARM_EnvOverTemp : 1|1@1+ (1,0) [0|1] ""  PC
 SG_ D2P_ALARM_MosOverTemp : 2|1@1+ (1,0) [0|1] ""  PC
 SG_ D2P_ALARM_MosExtreOverTemp : 3|1@1+ (1,0) [0|1] ""  PC
 SG_ D2P_ALARM_HighSideOverVolt : 4|1@1+ (1,0) [0|1] ""  PC
 SG_ D2P_ALARM_HighSideUnderVolt : 5|1@1+ (1,0) [0|1] ""  PC
 SG_ D2P_ALARM_LowSideOverVolt : 6|1@1+ (1,0) [0|1] ""  PC
 SG_ D2P_ALARM_HighSideOverCurr : 7|1@1+ (1,0) [0|1] ""  PC
 SG_ D2P_ALARM_LowSideOverCurr_HW : 8|1@1+ (1,0) [0|1] ""  PC
 SG_ D2P_ALARM_LowSideOverCurr_SW : 9|1@1+ (1,0) [0|1] ""  PC
 SG_ D2P_ALARM_SecSideOverCurr_HW : 10|1@1+ (1,0) [0|1] ""  PC
 SG_ D2P_ALARM_SecSideOverCurr_SW : 11|1@1+ (1,0) [0|1] ""  PC
 SG_ D2P_ALARM_PriSideOverCurr_HW : 12|1@1+ (1,0) [0|1] ""  PC
 SG_ D2P_ALARM_PriSideOverCurr_SW : 13|1@1+ (1,0) [0|1] ""  PC
 SG_ D2P_ALARM_LowPowerSupplyErr : 14|1@1+ (1,0) [0|1] ""  PC
 SG_ D2P_ALARM_MBMUComErr : 15|1@1+ (1,0) [0|1] ""  PC
 SG_ D2P_ALARM_DCDCMsTeSaplgErr : 16|1@1+ (1,0) [0|1] ""  PC
 SG_ D2P_ALARM_DCDCTeSaplgErr : 17|1@1+ (1,0) [0|1] ""  PC
 SG_ D2P_ALARM_VoltSamplingErr : 18|1@1+ (1,0) [0|1] ""  PC
 SG_ D2P_ALARM_HgSdCuSaplgErr : 19|1@1+ (1,0) [0|1] ""  PC
 SG_ D2P_ALARM_CtrlCurrSamplingErr : 20|1@1+ (1,0) [0|1] ""  PC
 SG_ D2P_ALARM_BypassFail : 21|1@1+ (1,0) [0|1] ""  PC
 SG_ D2P_ALARM_Reserve1 : 22|1@1+ (1,0) [0|1] ""  PC
 SG_ D2P_ALARM_Reserve2 : 23|1@1+ (1,0) [0|1] ""  PC
 SG_ D2P_ALARM_Reserve3 : 24|1@1+ (1,0) [0|1] ""  PC
 SG_ D2P_ALARM_Reserve4 : 25|1@1+ (1,0) [0|1] ""  PC
 SG_ D2P_ALARM_Reserve5 : 26|1@1+ (1,0) [0|1] ""  PC
 SG_ D2P_ALARM_Reserve6 : 27|1@1+ (1,0) [0|1] ""  PC
 SG_ D2P_ALARM_Reserve7 : 28|1@1+ (1,0) [0|1] ""  PC
 SG_ D2P_ALARM_Reserve8 : 29|1@1+ (1,0) [0|1] ""  PC
 SG_ D2P_ALARM_Reserve9 : 30|1@1+ (1,0) [0|1] ""  PC
 SG_ D2P_ALARM_Reserve10 : 31|1@1+ (1,0) [0|1] ""  PC
 SG_ D2P_ALARM_Reserve11 : 32|32@1+ (1,0) [0|4294967295] ""  PC

BO_ 2149547887 D2P_ALARM__47: 8 DCDC
 SG_ D2P_ALARM_EnvExtreOverTemp : 0|1@1+ (1,0) [0|1] ""  PC
 SG_ D2P_ALARM_EnvOverTemp : 1|1@1+ (1,0) [0|1] ""  PC
 SG_ D2P_ALARM_MosOverTemp : 2|1@1+ (1,0) [0|1] ""  PC
 SG_ D2P_ALARM_MosExtreOverTemp : 3|1@1+ (1,0) [0|1] ""  PC
 SG_ D2P_ALARM_HighSideOverVolt : 4|1@1+ (1,0) [0|1] ""  PC
 SG_ D2P_ALARM_HighSideUnderVolt : 5|1@1+ (1,0) [0|1] ""  PC
 SG_ D2P_ALARM_LowSideOverVolt : 6|1@1+ (1,0) [0|1] ""  PC
 SG_ D2P_ALARM_HighSideOverCurr : 7|1@1+ (1,0) [0|1] ""  PC
 SG_ D2P_ALARM_LowSideOverCurr_HW : 8|1@1+ (1,0) [0|1] ""  PC
 SG_ D2P_ALARM_LowSideOverCurr_SW : 9|1@1+ (1,0) [0|1] ""  PC
 SG_ D2P_ALARM_SecSideOverCurr_HW : 10|1@1+ (1,0) [0|1] ""  PC
 SG_ D2P_ALARM_SecSideOverCurr_SW : 11|1@1+ (1,0) [0|1] ""  PC
 SG_ D2P_ALARM_PriSideOverCurr_HW : 12|1@1+ (1,0) [0|1] ""  PC
 SG_ D2P_ALARM_PriSideOverCurr_SW : 13|1@1+ (1,0) [0|1] ""  PC
 SG_ D2P_ALARM_LowPowerSupplyErr : 14|1@1+ (1,0) [0|1] ""  PC
 SG_ D2P_ALARM_MBMUComErr : 15|1@1+ (1,0) [0|1] ""  PC
 SG_ D2P_ALARM_DCDCMsTeSaplgErr : 16|1@1+ (1,0) [0|1] ""  PC
 SG_ D2P_ALARM_DCDCTeSaplgErr : 17|1@1+ (1,0) [0|1] ""  PC
 SG_ D2P_ALARM_VoltSamplingErr : 18|1@1+ (1,0) [0|1] ""  PC
 SG_ D2P_ALARM_HgSdCuSaplgErr : 19|1@1+ (1,0) [0|1] ""  PC
 SG_ D2P_ALARM_CtrlCurrSamplingErr : 20|1@1+ (1,0) [0|1] ""  PC
 SG_ D2P_ALARM_BypassFail : 21|1@1+ (1,0) [0|1] ""  PC
 SG_ D2P_ALARM_Reserve1 : 22|1@1+ (1,0) [0|1] ""  PC
 SG_ D2P_ALARM_Reserve2 : 23|1@1+ (1,0) [0|1] ""  PC
 SG_ D2P_ALARM_Reserve3 : 24|1@1+ (1,0) [0|1] ""  PC
 SG_ D2P_ALARM_Reserve4 : 25|1@1+ (1,0) [0|1] ""  PC
 SG_ D2P_ALARM_Reserve5 : 26|1@1+ (1,0) [0|1] ""  PC
 SG_ D2P_ALARM_Reserve6 : 27|1@1+ (1,0) [0|1] ""  PC
 SG_ D2P_ALARM_Reserve7 : 28|1@1+ (1,0) [0|1] ""  PC
 SG_ D2P_ALARM_Reserve8 : 29|1@1+ (1,0) [0|1] ""  PC
 SG_ D2P_ALARM_Reserve9 : 30|1@1+ (1,0) [0|1] ""  PC
 SG_ D2P_ALARM_Reserve10 : 31|1@1+ (1,0) [0|1] ""  PC
 SG_ D2P_ALARM_Reserve11 : 32|32@1+ (1,0) [0|4294967295] ""  PC

BO_ 2149547888 D2P_ALARM__48: 8 DCDC
 SG_ D2P_ALARM_EnvExtreOverTemp : 0|1@1+ (1,0) [0|1] ""  PC
 SG_ D2P_ALARM_EnvOverTemp : 1|1@1+ (1,0) [0|1] ""  PC
 SG_ D2P_ALARM_MosOverTemp : 2|1@1+ (1,0) [0|1] ""  PC
 SG_ D2P_ALARM_MosExtreOverTemp : 3|1@1+ (1,0) [0|1] ""  PC
 SG_ D2P_ALARM_HighSideOverVolt : 4|1@1+ (1,0) [0|1] ""  PC
 SG_ D2P_ALARM_HighSideUnderVolt : 5|1@1+ (1,0) [0|1] ""  PC
 SG_ D2P_ALARM_LowSideOverVolt : 6|1@1+ (1,0) [0|1] ""  PC
 SG_ D2P_ALARM_HighSideOverCurr : 7|1@1+ (1,0) [0|1] ""  PC
 SG_ D2P_ALARM_LowSideOverCurr_HW : 8|1@1+ (1,0) [0|1] ""  PC
 SG_ D2P_ALARM_LowSideOverCurr_SW : 9|1@1+ (1,0) [0|1] ""  PC
 SG_ D2P_ALARM_SecSideOverCurr_HW : 10|1@1+ (1,0) [0|1] ""  PC
 SG_ D2P_ALARM_SecSideOverCurr_SW : 11|1@1+ (1,0) [0|1] ""  PC
 SG_ D2P_ALARM_PriSideOverCurr_HW : 12|1@1+ (1,0) [0|1] ""  PC
 SG_ D2P_ALARM_PriSideOverCurr_SW : 13|1@1+ (1,0) [0|1] ""  PC
 SG_ D2P_ALARM_LowPowerSupplyErr : 14|1@1+ (1,0) [0|1] ""  PC
 SG_ D2P_ALARM_MBMUComErr : 15|1@1+ (1,0) [0|1] ""  PC
 SG_ D2P_ALARM_DCDCMsTeSaplgErr : 16|1@1+ (1,0) [0|1] ""  PC
 SG_ D2P_ALARM_DCDCTeSaplgErr : 17|1@1+ (1,0) [0|1] ""  PC
 SG_ D2P_ALARM_VoltSamplingErr : 18|1@1+ (1,0) [0|1] ""  PC
 SG_ D2P_ALARM_HgSdCuSaplgErr : 19|1@1+ (1,0) [0|1] ""  PC
 SG_ D2P_ALARM_CtrlCurrSamplingErr : 20|1@1+ (1,0) [0|1] ""  PC
 SG_ D2P_ALARM_BypassFail : 21|1@1+ (1,0) [0|1] ""  PC
 SG_ D2P_ALARM_Reserve1 : 22|1@1+ (1,0) [0|1] ""  PC
 SG_ D2P_ALARM_Reserve2 : 23|1@1+ (1,0) [0|1] ""  PC
 SG_ D2P_ALARM_Reserve3 : 24|1@1+ (1,0) [0|1] ""  PC
 SG_ D2P_ALARM_Reserve4 : 25|1@1+ (1,0) [0|1] ""  PC
 SG_ D2P_ALARM_Reserve5 : 26|1@1+ (1,0) [0|1] ""  PC
 SG_ D2P_ALARM_Reserve6 : 27|1@1+ (1,0) [0|1] ""  PC
 SG_ D2P_ALARM_Reserve7 : 28|1@1+ (1,0) [0|1] ""  PC
 SG_ D2P_ALARM_Reserve8 : 29|1@1+ (1,0) [0|1] ""  PC
 SG_ D2P_ALARM_Reserve9 : 30|1@1+ (1,0) [0|1] ""  PC
 SG_ D2P_ALARM_Reserve10 : 31|1@1+ (1,0) [0|1] ""  PC
 SG_ D2P_ALARM_Reserve11 : 32|32@1+ (1,0) [0|4294967295] ""  PC

BO_ 2149547889 D2P_ALARM__49: 8 DCDC
 SG_ D2P_ALARM_EnvExtreOverTemp : 0|1@1+ (1,0) [0|1] ""  PC
 SG_ D2P_ALARM_EnvOverTemp : 1|1@1+ (1,0) [0|1] ""  PC
 SG_ D2P_ALARM_MosOverTemp : 2|1@1+ (1,0) [0|1] ""  PC
 SG_ D2P_ALARM_MosExtreOverTemp : 3|1@1+ (1,0) [0|1] ""  PC
 SG_ D2P_ALARM_HighSideOverVolt : 4|1@1+ (1,0) [0|1] ""  PC
 SG_ D2P_ALARM_HighSideUnderVolt : 5|1@1+ (1,0) [0|1] ""  PC
 SG_ D2P_ALARM_LowSideOverVolt : 6|1@1+ (1,0) [0|1] ""  PC
 SG_ D2P_ALARM_HighSideOverCurr : 7|1@1+ (1,0) [0|1] ""  PC
 SG_ D2P_ALARM_LowSideOverCurr_HW : 8|1@1+ (1,0) [0|1] ""  PC
 SG_ D2P_ALARM_LowSideOverCurr_SW : 9|1@1+ (1,0) [0|1] ""  PC
 SG_ D2P_ALARM_SecSideOverCurr_HW : 10|1@1+ (1,0) [0|1] ""  PC
 SG_ D2P_ALARM_SecSideOverCurr_SW : 11|1@1+ (1,0) [0|1] ""  PC
 SG_ D2P_ALARM_PriSideOverCurr_HW : 12|1@1+ (1,0) [0|1] ""  PC
 SG_ D2P_ALARM_PriSideOverCurr_SW : 13|1@1+ (1,0) [0|1] ""  PC
 SG_ D2P_ALARM_LowPowerSupplyErr : 14|1@1+ (1,0) [0|1] ""  PC
 SG_ D2P_ALARM_MBMUComErr : 15|1@1+ (1,0) [0|1] ""  PC
 SG_ D2P_ALARM_DCDCMsTeSaplgErr : 16|1@1+ (1,0) [0|1] ""  PC
 SG_ D2P_ALARM_DCDCTeSaplgErr : 17|1@1+ (1,0) [0|1] ""  PC
 SG_ D2P_ALARM_VoltSamplingErr : 18|1@1+ (1,0) [0|1] ""  PC
 SG_ D2P_ALARM_HgSdCuSaplgErr : 19|1@1+ (1,0) [0|1] ""  PC
 SG_ D2P_ALARM_CtrlCurrSamplingErr : 20|1@1+ (1,0) [0|1] ""  PC
 SG_ D2P_ALARM_BypassFail : 21|1@1+ (1,0) [0|1] ""  PC
 SG_ D2P_ALARM_Reserve1 : 22|1@1+ (1,0) [0|1] ""  PC
 SG_ D2P_ALARM_Reserve2 : 23|1@1+ (1,0) [0|1] ""  PC
 SG_ D2P_ALARM_Reserve3 : 24|1@1+ (1,0) [0|1] ""  PC
 SG_ D2P_ALARM_Reserve4 : 25|1@1+ (1,0) [0|1] ""  PC
 SG_ D2P_ALARM_Reserve5 : 26|1@1+ (1,0) [0|1] ""  PC
 SG_ D2P_ALARM_Reserve6 : 27|1@1+ (1,0) [0|1] ""  PC
 SG_ D2P_ALARM_Reserve7 : 28|1@1+ (1,0) [0|1] ""  PC
 SG_ D2P_ALARM_Reserve8 : 29|1@1+ (1,0) [0|1] ""  PC
 SG_ D2P_ALARM_Reserve9 : 30|1@1+ (1,0) [0|1] ""  PC
 SG_ D2P_ALARM_Reserve10 : 31|1@1+ (1,0) [0|1] ""  PC
 SG_ D2P_ALARM_Reserve11 : 32|32@1+ (1,0) [0|4294967295] ""  PC

BO_ 2149547890 D2P_ALARM__50: 8 DCDC
 SG_ D2P_ALARM_EnvExtreOverTemp : 0|1@1+ (1,0) [0|1] ""  PC
 SG_ D2P_ALARM_EnvOverTemp : 1|1@1+ (1,0) [0|1] ""  PC
 SG_ D2P_ALARM_MosOverTemp : 2|1@1+ (1,0) [0|1] ""  PC
 SG_ D2P_ALARM_MosExtreOverTemp : 3|1@1+ (1,0) [0|1] ""  PC
 SG_ D2P_ALARM_HighSideOverVolt : 4|1@1+ (1,0) [0|1] ""  PC
 SG_ D2P_ALARM_HighSideUnderVolt : 5|1@1+ (1,0) [0|1] ""  PC
 SG_ D2P_ALARM_LowSideOverVolt : 6|1@1+ (1,0) [0|1] ""  PC
 SG_ D2P_ALARM_HighSideOverCurr : 7|1@1+ (1,0) [0|1] ""  PC
 SG_ D2P_ALARM_LowSideOverCurr_HW : 8|1@1+ (1,0) [0|1] ""  PC
 SG_ D2P_ALARM_LowSideOverCurr_SW : 9|1@1+ (1,0) [0|1] ""  PC
 SG_ D2P_ALARM_SecSideOverCurr_HW : 10|1@1+ (1,0) [0|1] ""  PC
 SG_ D2P_ALARM_SecSideOverCurr_SW : 11|1@1+ (1,0) [0|1] ""  PC
 SG_ D2P_ALARM_PriSideOverCurr_HW : 12|1@1+ (1,0) [0|1] ""  PC
 SG_ D2P_ALARM_PriSideOverCurr_SW : 13|1@1+ (1,0) [0|1] ""  PC
 SG_ D2P_ALARM_LowPowerSupplyErr : 14|1@1+ (1,0) [0|1] ""  PC
 SG_ D2P_ALARM_MBMUComErr : 15|1@1+ (1,0) [0|1] ""  PC
 SG_ D2P_ALARM_DCDCMsTeSaplgErr : 16|1@1+ (1,0) [0|1] ""  PC
 SG_ D2P_ALARM_DCDCTeSaplgErr : 17|1@1+ (1,0) [0|1] ""  PC
 SG_ D2P_ALARM_VoltSamplingErr : 18|1@1+ (1,0) [0|1] ""  PC
 SG_ D2P_ALARM_HgSdCuSaplgErr : 19|1@1+ (1,0) [0|1] ""  PC
 SG_ D2P_ALARM_CtrlCurrSamplingErr : 20|1@1+ (1,0) [0|1] ""  PC
 SG_ D2P_ALARM_BypassFail : 21|1@1+ (1,0) [0|1] ""  PC
 SG_ D2P_ALARM_Reserve1 : 22|1@1+ (1,0) [0|1] ""  PC
 SG_ D2P_ALARM_Reserve2 : 23|1@1+ (1,0) [0|1] ""  PC
 SG_ D2P_ALARM_Reserve3 : 24|1@1+ (1,0) [0|1] ""  PC
 SG_ D2P_ALARM_Reserve4 : 25|1@1+ (1,0) [0|1] ""  PC
 SG_ D2P_ALARM_Reserve5 : 26|1@1+ (1,0) [0|1] ""  PC
 SG_ D2P_ALARM_Reserve6 : 27|1@1+ (1,0) [0|1] ""  PC
 SG_ D2P_ALARM_Reserve7 : 28|1@1+ (1,0) [0|1] ""  PC
 SG_ D2P_ALARM_Reserve8 : 29|1@1+ (1,0) [0|1] ""  PC
 SG_ D2P_ALARM_Reserve9 : 30|1@1+ (1,0) [0|1] ""  PC
 SG_ D2P_ALARM_Reserve10 : 31|1@1+ (1,0) [0|1] ""  PC
 SG_ D2P_ALARM_Reserve11 : 32|32@1+ (1,0) [0|4294967295] ""  PC

BO_ 2149547891 D2P_ALARM__51: 8 DCDC
 SG_ D2P_ALARM_EnvExtreOverTemp : 0|1@1+ (1,0) [0|1] ""  PC
 SG_ D2P_ALARM_EnvOverTemp : 1|1@1+ (1,0) [0|1] ""  PC
 SG_ D2P_ALARM_MosOverTemp : 2|1@1+ (1,0) [0|1] ""  PC
 SG_ D2P_ALARM_MosExtreOverTemp : 3|1@1+ (1,0) [0|1] ""  PC
 SG_ D2P_ALARM_HighSideOverVolt : 4|1@1+ (1,0) [0|1] ""  PC
 SG_ D2P_ALARM_HighSideUnderVolt : 5|1@1+ (1,0) [0|1] ""  PC
 SG_ D2P_ALARM_LowSideOverVolt : 6|1@1+ (1,0) [0|1] ""  PC
 SG_ D2P_ALARM_HighSideOverCurr : 7|1@1+ (1,0) [0|1] ""  PC
 SG_ D2P_ALARM_LowSideOverCurr_HW : 8|1@1+ (1,0) [0|1] ""  PC
 SG_ D2P_ALARM_LowSideOverCurr_SW : 9|1@1+ (1,0) [0|1] ""  PC
 SG_ D2P_ALARM_SecSideOverCurr_HW : 10|1@1+ (1,0) [0|1] ""  PC
 SG_ D2P_ALARM_SecSideOverCurr_SW : 11|1@1+ (1,0) [0|1] ""  PC
 SG_ D2P_ALARM_PriSideOverCurr_HW : 12|1@1+ (1,0) [0|1] ""  PC
 SG_ D2P_ALARM_PriSideOverCurr_SW : 13|1@1+ (1,0) [0|1] ""  PC
 SG_ D2P_ALARM_LowPowerSupplyErr : 14|1@1+ (1,0) [0|1] ""  PC
 SG_ D2P_ALARM_MBMUComErr : 15|1@1+ (1,0) [0|1] ""  PC
 SG_ D2P_ALARM_DCDCMsTeSaplgErr : 16|1@1+ (1,0) [0|1] ""  PC
 SG_ D2P_ALARM_DCDCTeSaplgErr : 17|1@1+ (1,0) [0|1] ""  PC
 SG_ D2P_ALARM_VoltSamplingErr : 18|1@1+ (1,0) [0|1] ""  PC
 SG_ D2P_ALARM_HgSdCuSaplgErr : 19|1@1+ (1,0) [0|1] ""  PC
 SG_ D2P_ALARM_CtrlCurrSamplingErr : 20|1@1+ (1,0) [0|1] ""  PC
 SG_ D2P_ALARM_BypassFail : 21|1@1+ (1,0) [0|1] ""  PC
 SG_ D2P_ALARM_Reserve1 : 22|1@1+ (1,0) [0|1] ""  PC
 SG_ D2P_ALARM_Reserve2 : 23|1@1+ (1,0) [0|1] ""  PC
 SG_ D2P_ALARM_Reserve3 : 24|1@1+ (1,0) [0|1] ""  PC
 SG_ D2P_ALARM_Reserve4 : 25|1@1+ (1,0) [0|1] ""  PC
 SG_ D2P_ALARM_Reserve5 : 26|1@1+ (1,0) [0|1] ""  PC
 SG_ D2P_ALARM_Reserve6 : 27|1@1+ (1,0) [0|1] ""  PC
 SG_ D2P_ALARM_Reserve7 : 28|1@1+ (1,0) [0|1] ""  PC
 SG_ D2P_ALARM_Reserve8 : 29|1@1+ (1,0) [0|1] ""  PC
 SG_ D2P_ALARM_Reserve9 : 30|1@1+ (1,0) [0|1] ""  PC
 SG_ D2P_ALARM_Reserve10 : 31|1@1+ (1,0) [0|1] ""  PC
 SG_ D2P_ALARM_Reserve11 : 32|32@1+ (1,0) [0|4294967295] ""  PC

BO_ 2149547892 D2P_ALARM__52: 8 DCDC
 SG_ D2P_ALARM_EnvExtreOverTemp : 0|1@1+ (1,0) [0|1] ""  PC
 SG_ D2P_ALARM_EnvOverTemp : 1|1@1+ (1,0) [0|1] ""  PC
 SG_ D2P_ALARM_MosOverTemp : 2|1@1+ (1,0) [0|1] ""  PC
 SG_ D2P_ALARM_MosExtreOverTemp : 3|1@1+ (1,0) [0|1] ""  PC
 SG_ D2P_ALARM_HighSideOverVolt : 4|1@1+ (1,0) [0|1] ""  PC
 SG_ D2P_ALARM_HighSideUnderVolt : 5|1@1+ (1,0) [0|1] ""  PC
 SG_ D2P_ALARM_LowSideOverVolt : 6|1@1+ (1,0) [0|1] ""  PC
 SG_ D2P_ALARM_HighSideOverCurr : 7|1@1+ (1,0) [0|1] ""  PC
 SG_ D2P_ALARM_LowSideOverCurr_HW : 8|1@1+ (1,0) [0|1] ""  PC
 SG_ D2P_ALARM_LowSideOverCurr_SW : 9|1@1+ (1,0) [0|1] ""  PC
 SG_ D2P_ALARM_SecSideOverCurr_HW : 10|1@1+ (1,0) [0|1] ""  PC
 SG_ D2P_ALARM_SecSideOverCurr_SW : 11|1@1+ (1,0) [0|1] ""  PC
 SG_ D2P_ALARM_PriSideOverCurr_HW : 12|1@1+ (1,0) [0|1] ""  PC
 SG_ D2P_ALARM_PriSideOverCurr_SW : 13|1@1+ (1,0) [0|1] ""  PC
 SG_ D2P_ALARM_LowPowerSupplyErr : 14|1@1+ (1,0) [0|1] ""  PC
 SG_ D2P_ALARM_MBMUComErr : 15|1@1+ (1,0) [0|1] ""  PC
 SG_ D2P_ALARM_DCDCMsTeSaplgErr : 16|1@1+ (1,0) [0|1] ""  PC
 SG_ D2P_ALARM_DCDCTeSaplgErr : 17|1@1+ (1,0) [0|1] ""  PC
 SG_ D2P_ALARM_VoltSamplingErr : 18|1@1+ (1,0) [0|1] ""  PC
 SG_ D2P_ALARM_HgSdCuSaplgErr : 19|1@1+ (1,0) [0|1] ""  PC
 SG_ D2P_ALARM_CtrlCurrSamplingErr : 20|1@1+ (1,0) [0|1] ""  PC
 SG_ D2P_ALARM_BypassFail : 21|1@1+ (1,0) [0|1] ""  PC
 SG_ D2P_ALARM_Reserve1 : 22|1@1+ (1,0) [0|1] ""  PC
 SG_ D2P_ALARM_Reserve2 : 23|1@1+ (1,0) [0|1] ""  PC
 SG_ D2P_ALARM_Reserve3 : 24|1@1+ (1,0) [0|1] ""  PC
 SG_ D2P_ALARM_Reserve4 : 25|1@1+ (1,0) [0|1] ""  PC
 SG_ D2P_ALARM_Reserve5 : 26|1@1+ (1,0) [0|1] ""  PC
 SG_ D2P_ALARM_Reserve6 : 27|1@1+ (1,0) [0|1] ""  PC
 SG_ D2P_ALARM_Reserve7 : 28|1@1+ (1,0) [0|1] ""  PC
 SG_ D2P_ALARM_Reserve8 : 29|1@1+ (1,0) [0|1] ""  PC
 SG_ D2P_ALARM_Reserve9 : 30|1@1+ (1,0) [0|1] ""  PC
 SG_ D2P_ALARM_Reserve10 : 31|1@1+ (1,0) [0|1] ""  PC
 SG_ D2P_ALARM_Reserve11 : 32|32@1+ (1,0) [0|4294967295] ""  PC

BO_ 2149547893 D2P_ALARM__53: 8 DCDC
 SG_ D2P_ALARM_EnvExtreOverTemp : 0|1@1+ (1,0) [0|1] ""  PC
 SG_ D2P_ALARM_EnvOverTemp : 1|1@1+ (1,0) [0|1] ""  PC
 SG_ D2P_ALARM_MosOverTemp : 2|1@1+ (1,0) [0|1] ""  PC
 SG_ D2P_ALARM_MosExtreOverTemp : 3|1@1+ (1,0) [0|1] ""  PC
 SG_ D2P_ALARM_HighSideOverVolt : 4|1@1+ (1,0) [0|1] ""  PC
 SG_ D2P_ALARM_HighSideUnderVolt : 5|1@1+ (1,0) [0|1] ""  PC
 SG_ D2P_ALARM_LowSideOverVolt : 6|1@1+ (1,0) [0|1] ""  PC
 SG_ D2P_ALARM_HighSideOverCurr : 7|1@1+ (1,0) [0|1] ""  PC
 SG_ D2P_ALARM_LowSideOverCurr_HW : 8|1@1+ (1,0) [0|1] ""  PC
 SG_ D2P_ALARM_LowSideOverCurr_SW : 9|1@1+ (1,0) [0|1] ""  PC
 SG_ D2P_ALARM_SecSideOverCurr_HW : 10|1@1+ (1,0) [0|1] ""  PC
 SG_ D2P_ALARM_SecSideOverCurr_SW : 11|1@1+ (1,0) [0|1] ""  PC
 SG_ D2P_ALARM_PriSideOverCurr_HW : 12|1@1+ (1,0) [0|1] ""  PC
 SG_ D2P_ALARM_PriSideOverCurr_SW : 13|1@1+ (1,0) [0|1] ""  PC
 SG_ D2P_ALARM_LowPowerSupplyErr : 14|1@1+ (1,0) [0|1] ""  PC
 SG_ D2P_ALARM_MBMUComErr : 15|1@1+ (1,0) [0|1] ""  PC
 SG_ D2P_ALARM_DCDCMsTeSaplgErr : 16|1@1+ (1,0) [0|1] ""  PC
 SG_ D2P_ALARM_DCDCTeSaplgErr : 17|1@1+ (1,0) [0|1] ""  PC
 SG_ D2P_ALARM_VoltSamplingErr : 18|1@1+ (1,0) [0|1] ""  PC
 SG_ D2P_ALARM_HgSdCuSaplgErr : 19|1@1+ (1,0) [0|1] ""  PC
 SG_ D2P_ALARM_CtrlCurrSamplingErr : 20|1@1+ (1,0) [0|1] ""  PC
 SG_ D2P_ALARM_BypassFail : 21|1@1+ (1,0) [0|1] ""  PC
 SG_ D2P_ALARM_Reserve1 : 22|1@1+ (1,0) [0|1] ""  PC
 SG_ D2P_ALARM_Reserve2 : 23|1@1+ (1,0) [0|1] ""  PC
 SG_ D2P_ALARM_Reserve3 : 24|1@1+ (1,0) [0|1] ""  PC
 SG_ D2P_ALARM_Reserve4 : 25|1@1+ (1,0) [0|1] ""  PC
 SG_ D2P_ALARM_Reserve5 : 26|1@1+ (1,0) [0|1] ""  PC
 SG_ D2P_ALARM_Reserve6 : 27|1@1+ (1,0) [0|1] ""  PC
 SG_ D2P_ALARM_Reserve7 : 28|1@1+ (1,0) [0|1] ""  PC
 SG_ D2P_ALARM_Reserve8 : 29|1@1+ (1,0) [0|1] ""  PC
 SG_ D2P_ALARM_Reserve9 : 30|1@1+ (1,0) [0|1] ""  PC
 SG_ D2P_ALARM_Reserve10 : 31|1@1+ (1,0) [0|1] ""  PC
 SG_ D2P_ALARM_Reserve11 : 32|32@1+ (1,0) [0|4294967295] ""  PC

BO_ 2149547894 D2P_ALARM__54: 8 DCDC
 SG_ D2P_ALARM_EnvExtreOverTemp : 0|1@1+ (1,0) [0|1] ""  PC
 SG_ D2P_ALARM_EnvOverTemp : 1|1@1+ (1,0) [0|1] ""  PC
 SG_ D2P_ALARM_MosOverTemp : 2|1@1+ (1,0) [0|1] ""  PC
 SG_ D2P_ALARM_MosExtreOverTemp : 3|1@1+ (1,0) [0|1] ""  PC
 SG_ D2P_ALARM_HighSideOverVolt : 4|1@1+ (1,0) [0|1] ""  PC
 SG_ D2P_ALARM_HighSideUnderVolt : 5|1@1+ (1,0) [0|1] ""  PC
 SG_ D2P_ALARM_LowSideOverVolt : 6|1@1+ (1,0) [0|1] ""  PC
 SG_ D2P_ALARM_HighSideOverCurr : 7|1@1+ (1,0) [0|1] ""  PC
 SG_ D2P_ALARM_LowSideOverCurr_HW : 8|1@1+ (1,0) [0|1] ""  PC
 SG_ D2P_ALARM_LowSideOverCurr_SW : 9|1@1+ (1,0) [0|1] ""  PC
 SG_ D2P_ALARM_SecSideOverCurr_HW : 10|1@1+ (1,0) [0|1] ""  PC
 SG_ D2P_ALARM_SecSideOverCurr_SW : 11|1@1+ (1,0) [0|1] ""  PC
 SG_ D2P_ALARM_PriSideOverCurr_HW : 12|1@1+ (1,0) [0|1] ""  PC
 SG_ D2P_ALARM_PriSideOverCurr_SW : 13|1@1+ (1,0) [0|1] ""  PC
 SG_ D2P_ALARM_LowPowerSupplyErr : 14|1@1+ (1,0) [0|1] ""  PC
 SG_ D2P_ALARM_MBMUComErr : 15|1@1+ (1,0) [0|1] ""  PC
 SG_ D2P_ALARM_DCDCMsTeSaplgErr : 16|1@1+ (1,0) [0|1] ""  PC
 SG_ D2P_ALARM_DCDCTeSaplgErr : 17|1@1+ (1,0) [0|1] ""  PC
 SG_ D2P_ALARM_VoltSamplingErr : 18|1@1+ (1,0) [0|1] ""  PC
 SG_ D2P_ALARM_HgSdCuSaplgErr : 19|1@1+ (1,0) [0|1] ""  PC
 SG_ D2P_ALARM_CtrlCurrSamplingErr : 20|1@1+ (1,0) [0|1] ""  PC
 SG_ D2P_ALARM_BypassFail : 21|1@1+ (1,0) [0|1] ""  PC
 SG_ D2P_ALARM_Reserve1 : 22|1@1+ (1,0) [0|1] ""  PC
 SG_ D2P_ALARM_Reserve2 : 23|1@1+ (1,0) [0|1] ""  PC
 SG_ D2P_ALARM_Reserve3 : 24|1@1+ (1,0) [0|1] ""  PC
 SG_ D2P_ALARM_Reserve4 : 25|1@1+ (1,0) [0|1] ""  PC
 SG_ D2P_ALARM_Reserve5 : 26|1@1+ (1,0) [0|1] ""  PC
 SG_ D2P_ALARM_Reserve6 : 27|1@1+ (1,0) [0|1] ""  PC
 SG_ D2P_ALARM_Reserve7 : 28|1@1+ (1,0) [0|1] ""  PC
 SG_ D2P_ALARM_Reserve8 : 29|1@1+ (1,0) [0|1] ""  PC
 SG_ D2P_ALARM_Reserve9 : 30|1@1+ (1,0) [0|1] ""  PC
 SG_ D2P_ALARM_Reserve10 : 31|1@1+ (1,0) [0|1] ""  PC
 SG_ D2P_ALARM_Reserve11 : 32|32@1+ (1,0) [0|4294967295] ""  PC

BO_ 2149547895 D2P_ALARM__55: 8 DCDC
 SG_ D2P_ALARM_EnvExtreOverTemp : 0|1@1+ (1,0) [0|1] ""  PC
 SG_ D2P_ALARM_EnvOverTemp : 1|1@1+ (1,0) [0|1] ""  PC
 SG_ D2P_ALARM_MosOverTemp : 2|1@1+ (1,0) [0|1] ""  PC
 SG_ D2P_ALARM_MosExtreOverTemp : 3|1@1+ (1,0) [0|1] ""  PC
 SG_ D2P_ALARM_HighSideOverVolt : 4|1@1+ (1,0) [0|1] ""  PC
 SG_ D2P_ALARM_HighSideUnderVolt : 5|1@1+ (1,0) [0|1] ""  PC
 SG_ D2P_ALARM_LowSideOverVolt : 6|1@1+ (1,0) [0|1] ""  PC
 SG_ D2P_ALARM_HighSideOverCurr : 7|1@1+ (1,0) [0|1] ""  PC
 SG_ D2P_ALARM_LowSideOverCurr_HW : 8|1@1+ (1,0) [0|1] ""  PC
 SG_ D2P_ALARM_LowSideOverCurr_SW : 9|1@1+ (1,0) [0|1] ""  PC
 SG_ D2P_ALARM_SecSideOverCurr_HW : 10|1@1+ (1,0) [0|1] ""  PC
 SG_ D2P_ALARM_SecSideOverCurr_SW : 11|1@1+ (1,0) [0|1] ""  PC
 SG_ D2P_ALARM_PriSideOverCurr_HW : 12|1@1+ (1,0) [0|1] ""  PC
 SG_ D2P_ALARM_PriSideOverCurr_SW : 13|1@1+ (1,0) [0|1] ""  PC
 SG_ D2P_ALARM_LowPowerSupplyErr : 14|1@1+ (1,0) [0|1] ""  PC
 SG_ D2P_ALARM_MBMUComErr : 15|1@1+ (1,0) [0|1] ""  PC
 SG_ D2P_ALARM_DCDCMsTeSaplgErr : 16|1@1+ (1,0) [0|1] ""  PC
 SG_ D2P_ALARM_DCDCTeSaplgErr : 17|1@1+ (1,0) [0|1] ""  PC
 SG_ D2P_ALARM_VoltSamplingErr : 18|1@1+ (1,0) [0|1] ""  PC
 SG_ D2P_ALARM_HgSdCuSaplgErr : 19|1@1+ (1,0) [0|1] ""  PC
 SG_ D2P_ALARM_CtrlCurrSamplingErr : 20|1@1+ (1,0) [0|1] ""  PC
 SG_ D2P_ALARM_BypassFail : 21|1@1+ (1,0) [0|1] ""  PC
 SG_ D2P_ALARM_Reserve1 : 22|1@1+ (1,0) [0|1] ""  PC
 SG_ D2P_ALARM_Reserve2 : 23|1@1+ (1,0) [0|1] ""  PC
 SG_ D2P_ALARM_Reserve3 : 24|1@1+ (1,0) [0|1] ""  PC
 SG_ D2P_ALARM_Reserve4 : 25|1@1+ (1,0) [0|1] ""  PC
 SG_ D2P_ALARM_Reserve5 : 26|1@1+ (1,0) [0|1] ""  PC
 SG_ D2P_ALARM_Reserve6 : 27|1@1+ (1,0) [0|1] ""  PC
 SG_ D2P_ALARM_Reserve7 : 28|1@1+ (1,0) [0|1] ""  PC
 SG_ D2P_ALARM_Reserve8 : 29|1@1+ (1,0) [0|1] ""  PC
 SG_ D2P_ALARM_Reserve9 : 30|1@1+ (1,0) [0|1] ""  PC
 SG_ D2P_ALARM_Reserve10 : 31|1@1+ (1,0) [0|1] ""  PC
 SG_ D2P_ALARM_Reserve11 : 32|32@1+ (1,0) [0|4294967295] ""  PC

BO_ 2149547896 D2P_ALARM__56: 8 DCDC
 SG_ D2P_ALARM_EnvExtreOverTemp : 0|1@1+ (1,0) [0|1] ""  PC
 SG_ D2P_ALARM_EnvOverTemp : 1|1@1+ (1,0) [0|1] ""  PC
 SG_ D2P_ALARM_MosOverTemp : 2|1@1+ (1,0) [0|1] ""  PC
 SG_ D2P_ALARM_MosExtreOverTemp : 3|1@1+ (1,0) [0|1] ""  PC
 SG_ D2P_ALARM_HighSideOverVolt : 4|1@1+ (1,0) [0|1] ""  PC
 SG_ D2P_ALARM_HighSideUnderVolt : 5|1@1+ (1,0) [0|1] ""  PC
 SG_ D2P_ALARM_LowSideOverVolt : 6|1@1+ (1,0) [0|1] ""  PC
 SG_ D2P_ALARM_HighSideOverCurr : 7|1@1+ (1,0) [0|1] ""  PC
 SG_ D2P_ALARM_LowSideOverCurr_HW : 8|1@1+ (1,0) [0|1] ""  PC
 SG_ D2P_ALARM_LowSideOverCurr_SW : 9|1@1+ (1,0) [0|1] ""  PC
 SG_ D2P_ALARM_SecSideOverCurr_HW : 10|1@1+ (1,0) [0|1] ""  PC
 SG_ D2P_ALARM_SecSideOverCurr_SW : 11|1@1+ (1,0) [0|1] ""  PC
 SG_ D2P_ALARM_PriSideOverCurr_HW : 12|1@1+ (1,0) [0|1] ""  PC
 SG_ D2P_ALARM_PriSideOverCurr_SW : 13|1@1+ (1,0) [0|1] ""  PC
 SG_ D2P_ALARM_LowPowerSupplyErr : 14|1@1+ (1,0) [0|1] ""  PC
 SG_ D2P_ALARM_MBMUComErr : 15|1@1+ (1,0) [0|1] ""  PC
 SG_ D2P_ALARM_DCDCMsTeSaplgErr : 16|1@1+ (1,0) [0|1] ""  PC
 SG_ D2P_ALARM_DCDCTeSaplgErr : 17|1@1+ (1,0) [0|1] ""  PC
 SG_ D2P_ALARM_VoltSamplingErr : 18|1@1+ (1,0) [0|1] ""  PC
 SG_ D2P_ALARM_HgSdCuSaplgErr : 19|1@1+ (1,0) [0|1] ""  PC
 SG_ D2P_ALARM_CtrlCurrSamplingErr : 20|1@1+ (1,0) [0|1] ""  PC
 SG_ D2P_ALARM_BypassFail : 21|1@1+ (1,0) [0|1] ""  PC
 SG_ D2P_ALARM_Reserve1 : 22|1@1+ (1,0) [0|1] ""  PC
 SG_ D2P_ALARM_Reserve2 : 23|1@1+ (1,0) [0|1] ""  PC
 SG_ D2P_ALARM_Reserve3 : 24|1@1+ (1,0) [0|1] ""  PC
 SG_ D2P_ALARM_Reserve4 : 25|1@1+ (1,0) [0|1] ""  PC
 SG_ D2P_ALARM_Reserve5 : 26|1@1+ (1,0) [0|1] ""  PC
 SG_ D2P_ALARM_Reserve6 : 27|1@1+ (1,0) [0|1] ""  PC
 SG_ D2P_ALARM_Reserve7 : 28|1@1+ (1,0) [0|1] ""  PC
 SG_ D2P_ALARM_Reserve8 : 29|1@1+ (1,0) [0|1] ""  PC
 SG_ D2P_ALARM_Reserve9 : 30|1@1+ (1,0) [0|1] ""  PC
 SG_ D2P_ALARM_Reserve10 : 31|1@1+ (1,0) [0|1] ""  PC
 SG_ D2P_ALARM_Reserve11 : 32|32@1+ (1,0) [0|4294967295] ""  PC

BO_ 2149547897 D2P_ALARM__57: 8 DCDC
 SG_ D2P_ALARM_EnvExtreOverTemp : 0|1@1+ (1,0) [0|1] ""  PC
 SG_ D2P_ALARM_EnvOverTemp : 1|1@1+ (1,0) [0|1] ""  PC
 SG_ D2P_ALARM_MosOverTemp : 2|1@1+ (1,0) [0|1] ""  PC
 SG_ D2P_ALARM_MosExtreOverTemp : 3|1@1+ (1,0) [0|1] ""  PC
 SG_ D2P_ALARM_HighSideOverVolt : 4|1@1+ (1,0) [0|1] ""  PC
 SG_ D2P_ALARM_HighSideUnderVolt : 5|1@1+ (1,0) [0|1] ""  PC
 SG_ D2P_ALARM_LowSideOverVolt : 6|1@1+ (1,0) [0|1] ""  PC
 SG_ D2P_ALARM_HighSideOverCurr : 7|1@1+ (1,0) [0|1] ""  PC
 SG_ D2P_ALARM_LowSideOverCurr_HW : 8|1@1+ (1,0) [0|1] ""  PC
 SG_ D2P_ALARM_LowSideOverCurr_SW : 9|1@1+ (1,0) [0|1] ""  PC
 SG_ D2P_ALARM_SecSideOverCurr_HW : 10|1@1+ (1,0) [0|1] ""  PC
 SG_ D2P_ALARM_SecSideOverCurr_SW : 11|1@1+ (1,0) [0|1] ""  PC
 SG_ D2P_ALARM_PriSideOverCurr_HW : 12|1@1+ (1,0) [0|1] ""  PC
 SG_ D2P_ALARM_PriSideOverCurr_SW : 13|1@1+ (1,0) [0|1] ""  PC
 SG_ D2P_ALARM_LowPowerSupplyErr : 14|1@1+ (1,0) [0|1] ""  PC
 SG_ D2P_ALARM_MBMUComErr : 15|1@1+ (1,0) [0|1] ""  PC
 SG_ D2P_ALARM_DCDCMsTeSaplgErr : 16|1@1+ (1,0) [0|1] ""  PC
 SG_ D2P_ALARM_DCDCTeSaplgErr : 17|1@1+ (1,0) [0|1] ""  PC
 SG_ D2P_ALARM_VoltSamplingErr : 18|1@1+ (1,0) [0|1] ""  PC
 SG_ D2P_ALARM_HgSdCuSaplgErr : 19|1@1+ (1,0) [0|1] ""  PC
 SG_ D2P_ALARM_CtrlCurrSamplingErr : 20|1@1+ (1,0) [0|1] ""  PC
 SG_ D2P_ALARM_BypassFail : 21|1@1+ (1,0) [0|1] ""  PC
 SG_ D2P_ALARM_Reserve1 : 22|1@1+ (1,0) [0|1] ""  PC
 SG_ D2P_ALARM_Reserve2 : 23|1@1+ (1,0) [0|1] ""  PC
 SG_ D2P_ALARM_Reserve3 : 24|1@1+ (1,0) [0|1] ""  PC
 SG_ D2P_ALARM_Reserve4 : 25|1@1+ (1,0) [0|1] ""  PC
 SG_ D2P_ALARM_Reserve5 : 26|1@1+ (1,0) [0|1] ""  PC
 SG_ D2P_ALARM_Reserve6 : 27|1@1+ (1,0) [0|1] ""  PC
 SG_ D2P_ALARM_Reserve7 : 28|1@1+ (1,0) [0|1] ""  PC
 SG_ D2P_ALARM_Reserve8 : 29|1@1+ (1,0) [0|1] ""  PC
 SG_ D2P_ALARM_Reserve9 : 30|1@1+ (1,0) [0|1] ""  PC
 SG_ D2P_ALARM_Reserve10 : 31|1@1+ (1,0) [0|1] ""  PC
 SG_ D2P_ALARM_Reserve11 : 32|32@1+ (1,0) [0|4294967295] ""  PC

BO_ 2149547898 D2P_ALARM__58: 8 DCDC
 SG_ D2P_ALARM_EnvExtreOverTemp : 0|1@1+ (1,0) [0|1] ""  PC
 SG_ D2P_ALARM_EnvOverTemp : 1|1@1+ (1,0) [0|1] ""  PC
 SG_ D2P_ALARM_MosOverTemp : 2|1@1+ (1,0) [0|1] ""  PC
 SG_ D2P_ALARM_MosExtreOverTemp : 3|1@1+ (1,0) [0|1] ""  PC
 SG_ D2P_ALARM_HighSideOverVolt : 4|1@1+ (1,0) [0|1] ""  PC
 SG_ D2P_ALARM_HighSideUnderVolt : 5|1@1+ (1,0) [0|1] ""  PC
 SG_ D2P_ALARM_LowSideOverVolt : 6|1@1+ (1,0) [0|1] ""  PC
 SG_ D2P_ALARM_HighSideOverCurr : 7|1@1+ (1,0) [0|1] ""  PC
 SG_ D2P_ALARM_LowSideOverCurr_HW : 8|1@1+ (1,0) [0|1] ""  PC
 SG_ D2P_ALARM_LowSideOverCurr_SW : 9|1@1+ (1,0) [0|1] ""  PC
 SG_ D2P_ALARM_SecSideOverCurr_HW : 10|1@1+ (1,0) [0|1] ""  PC
 SG_ D2P_ALARM_SecSideOverCurr_SW : 11|1@1+ (1,0) [0|1] ""  PC
 SG_ D2P_ALARM_PriSideOverCurr_HW : 12|1@1+ (1,0) [0|1] ""  PC
 SG_ D2P_ALARM_PriSideOverCurr_SW : 13|1@1+ (1,0) [0|1] ""  PC
 SG_ D2P_ALARM_LowPowerSupplyErr : 14|1@1+ (1,0) [0|1] ""  PC
 SG_ D2P_ALARM_MBMUComErr : 15|1@1+ (1,0) [0|1] ""  PC
 SG_ D2P_ALARM_DCDCMsTeSaplgErr : 16|1@1+ (1,0) [0|1] ""  PC
 SG_ D2P_ALARM_DCDCTeSaplgErr : 17|1@1+ (1,0) [0|1] ""  PC
 SG_ D2P_ALARM_VoltSamplingErr : 18|1@1+ (1,0) [0|1] ""  PC
 SG_ D2P_ALARM_HgSdCuSaplgErr : 19|1@1+ (1,0) [0|1] ""  PC
 SG_ D2P_ALARM_CtrlCurrSamplingErr : 20|1@1+ (1,0) [0|1] ""  PC
 SG_ D2P_ALARM_BypassFail : 21|1@1+ (1,0) [0|1] ""  PC
 SG_ D2P_ALARM_Reserve1 : 22|1@1+ (1,0) [0|1] ""  PC
 SG_ D2P_ALARM_Reserve2 : 23|1@1+ (1,0) [0|1] ""  PC
 SG_ D2P_ALARM_Reserve3 : 24|1@1+ (1,0) [0|1] ""  PC
 SG_ D2P_ALARM_Reserve4 : 25|1@1+ (1,0) [0|1] ""  PC
 SG_ D2P_ALARM_Reserve5 : 26|1@1+ (1,0) [0|1] ""  PC
 SG_ D2P_ALARM_Reserve6 : 27|1@1+ (1,0) [0|1] ""  PC
 SG_ D2P_ALARM_Reserve7 : 28|1@1+ (1,0) [0|1] ""  PC
 SG_ D2P_ALARM_Reserve8 : 29|1@1+ (1,0) [0|1] ""  PC
 SG_ D2P_ALARM_Reserve9 : 30|1@1+ (1,0) [0|1] ""  PC
 SG_ D2P_ALARM_Reserve10 : 31|1@1+ (1,0) [0|1] ""  PC
 SG_ D2P_ALARM_Reserve11 : 32|32@1+ (1,0) [0|4294967295] ""  PC

BO_ 2149547899 D2P_ALARM__59: 8 DCDC
 SG_ D2P_ALARM_EnvExtreOverTemp : 0|1@1+ (1,0) [0|1] ""  PC
 SG_ D2P_ALARM_EnvOverTemp : 1|1@1+ (1,0) [0|1] ""  PC
 SG_ D2P_ALARM_MosOverTemp : 2|1@1+ (1,0) [0|1] ""  PC
 SG_ D2P_ALARM_MosExtreOverTemp : 3|1@1+ (1,0) [0|1] ""  PC
 SG_ D2P_ALARM_HighSideOverVolt : 4|1@1+ (1,0) [0|1] ""  PC
 SG_ D2P_ALARM_HighSideUnderVolt : 5|1@1+ (1,0) [0|1] ""  PC
 SG_ D2P_ALARM_LowSideOverVolt : 6|1@1+ (1,0) [0|1] ""  PC
 SG_ D2P_ALARM_HighSideOverCurr : 7|1@1+ (1,0) [0|1] ""  PC
 SG_ D2P_ALARM_LowSideOverCurr_HW : 8|1@1+ (1,0) [0|1] ""  PC
 SG_ D2P_ALARM_LowSideOverCurr_SW : 9|1@1+ (1,0) [0|1] ""  PC
 SG_ D2P_ALARM_SecSideOverCurr_HW : 10|1@1+ (1,0) [0|1] ""  PC
 SG_ D2P_ALARM_SecSideOverCurr_SW : 11|1@1+ (1,0) [0|1] ""  PC
 SG_ D2P_ALARM_PriSideOverCurr_HW : 12|1@1+ (1,0) [0|1] ""  PC
 SG_ D2P_ALARM_PriSideOverCurr_SW : 13|1@1+ (1,0) [0|1] ""  PC
 SG_ D2P_ALARM_LowPowerSupplyErr : 14|1@1+ (1,0) [0|1] ""  PC
 SG_ D2P_ALARM_MBMUComErr : 15|1@1+ (1,0) [0|1] ""  PC
 SG_ D2P_ALARM_DCDCMsTeSaplgErr : 16|1@1+ (1,0) [0|1] ""  PC
 SG_ D2P_ALARM_DCDCTeSaplgErr : 17|1@1+ (1,0) [0|1] ""  PC
 SG_ D2P_ALARM_VoltSamplingErr : 18|1@1+ (1,0) [0|1] ""  PC
 SG_ D2P_ALARM_HgSdCuSaplgErr : 19|1@1+ (1,0) [0|1] ""  PC
 SG_ D2P_ALARM_CtrlCurrSamplingErr : 20|1@1+ (1,0) [0|1] ""  PC
 SG_ D2P_ALARM_BypassFail : 21|1@1+ (1,0) [0|1] ""  PC
 SG_ D2P_ALARM_Reserve1 : 22|1@1+ (1,0) [0|1] ""  PC
 SG_ D2P_ALARM_Reserve2 : 23|1@1+ (1,0) [0|1] ""  PC
 SG_ D2P_ALARM_Reserve3 : 24|1@1+ (1,0) [0|1] ""  PC
 SG_ D2P_ALARM_Reserve4 : 25|1@1+ (1,0) [0|1] ""  PC
 SG_ D2P_ALARM_Reserve5 : 26|1@1+ (1,0) [0|1] ""  PC
 SG_ D2P_ALARM_Reserve6 : 27|1@1+ (1,0) [0|1] ""  PC
 SG_ D2P_ALARM_Reserve7 : 28|1@1+ (1,0) [0|1] ""  PC
 SG_ D2P_ALARM_Reserve8 : 29|1@1+ (1,0) [0|1] ""  PC
 SG_ D2P_ALARM_Reserve9 : 30|1@1+ (1,0) [0|1] ""  PC
 SG_ D2P_ALARM_Reserve10 : 31|1@1+ (1,0) [0|1] ""  PC
 SG_ D2P_ALARM_Reserve11 : 32|32@1+ (1,0) [0|4294967295] ""  PC

BO_ 2149547900 D2P_ALARM__60: 8 DCDC
 SG_ D2P_ALARM_EnvExtreOverTemp : 0|1@1+ (1,0) [0|1] ""  PC
 SG_ D2P_ALARM_EnvOverTemp : 1|1@1+ (1,0) [0|1] ""  PC
 SG_ D2P_ALARM_MosOverTemp : 2|1@1+ (1,0) [0|1] ""  PC
 SG_ D2P_ALARM_MosExtreOverTemp : 3|1@1+ (1,0) [0|1] ""  PC
 SG_ D2P_ALARM_HighSideOverVolt : 4|1@1+ (1,0) [0|1] ""  PC
 SG_ D2P_ALARM_HighSideUnderVolt : 5|1@1+ (1,0) [0|1] ""  PC
 SG_ D2P_ALARM_LowSideOverVolt : 6|1@1+ (1,0) [0|1] ""  PC
 SG_ D2P_ALARM_HighSideOverCurr : 7|1@1+ (1,0) [0|1] ""  PC
 SG_ D2P_ALARM_LowSideOverCurr_HW : 8|1@1+ (1,0) [0|1] ""  PC
 SG_ D2P_ALARM_LowSideOverCurr_SW : 9|1@1+ (1,0) [0|1] ""  PC
 SG_ D2P_ALARM_SecSideOverCurr_HW : 10|1@1+ (1,0) [0|1] ""  PC
 SG_ D2P_ALARM_SecSideOverCurr_SW : 11|1@1+ (1,0) [0|1] ""  PC
 SG_ D2P_ALARM_PriSideOverCurr_HW : 12|1@1+ (1,0) [0|1] ""  PC
 SG_ D2P_ALARM_PriSideOverCurr_SW : 13|1@1+ (1,0) [0|1] ""  PC
 SG_ D2P_ALARM_LowPowerSupplyErr : 14|1@1+ (1,0) [0|1] ""  PC
 SG_ D2P_ALARM_MBMUComErr : 15|1@1+ (1,0) [0|1] ""  PC
 SG_ D2P_ALARM_DCDCMsTeSaplgErr : 16|1@1+ (1,0) [0|1] ""  PC
 SG_ D2P_ALARM_DCDCTeSaplgErr : 17|1@1+ (1,0) [0|1] ""  PC
 SG_ D2P_ALARM_VoltSamplingErr : 18|1@1+ (1,0) [0|1] ""  PC
 SG_ D2P_ALARM_HgSdCuSaplgErr : 19|1@1+ (1,0) [0|1] ""  PC
 SG_ D2P_ALARM_CtrlCurrSamplingErr : 20|1@1+ (1,0) [0|1] ""  PC
 SG_ D2P_ALARM_BypassFail : 21|1@1+ (1,0) [0|1] ""  PC
 SG_ D2P_ALARM_Reserve1 : 22|1@1+ (1,0) [0|1] ""  PC
 SG_ D2P_ALARM_Reserve2 : 23|1@1+ (1,0) [0|1] ""  PC
 SG_ D2P_ALARM_Reserve3 : 24|1@1+ (1,0) [0|1] ""  PC
 SG_ D2P_ALARM_Reserve4 : 25|1@1+ (1,0) [0|1] ""  PC
 SG_ D2P_ALARM_Reserve5 : 26|1@1+ (1,0) [0|1] ""  PC
 SG_ D2P_ALARM_Reserve6 : 27|1@1+ (1,0) [0|1] ""  PC
 SG_ D2P_ALARM_Reserve7 : 28|1@1+ (1,0) [0|1] ""  PC
 SG_ D2P_ALARM_Reserve8 : 29|1@1+ (1,0) [0|1] ""  PC
 SG_ D2P_ALARM_Reserve9 : 30|1@1+ (1,0) [0|1] ""  PC
 SG_ D2P_ALARM_Reserve10 : 31|1@1+ (1,0) [0|1] ""  PC
 SG_ D2P_ALARM_Reserve11 : 32|32@1+ (1,0) [0|4294967295] ""  PC

BO_ 2149547901 D2P_ALARM__61: 8 DCDC
 SG_ D2P_ALARM_EnvExtreOverTemp : 0|1@1+ (1,0) [0|1] ""  PC
 SG_ D2P_ALARM_EnvOverTemp : 1|1@1+ (1,0) [0|1] ""  PC
 SG_ D2P_ALARM_MosOverTemp : 2|1@1+ (1,0) [0|1] ""  PC
 SG_ D2P_ALARM_MosExtreOverTemp : 3|1@1+ (1,0) [0|1] ""  PC
 SG_ D2P_ALARM_HighSideOverVolt : 4|1@1+ (1,0) [0|1] ""  PC
 SG_ D2P_ALARM_HighSideUnderVolt : 5|1@1+ (1,0) [0|1] ""  PC
 SG_ D2P_ALARM_LowSideOverVolt : 6|1@1+ (1,0) [0|1] ""  PC
 SG_ D2P_ALARM_HighSideOverCurr : 7|1@1+ (1,0) [0|1] ""  PC
 SG_ D2P_ALARM_LowSideOverCurr_HW : 8|1@1+ (1,0) [0|1] ""  PC
 SG_ D2P_ALARM_LowSideOverCurr_SW : 9|1@1+ (1,0) [0|1] ""  PC
 SG_ D2P_ALARM_SecSideOverCurr_HW : 10|1@1+ (1,0) [0|1] ""  PC
 SG_ D2P_ALARM_SecSideOverCurr_SW : 11|1@1+ (1,0) [0|1] ""  PC
 SG_ D2P_ALARM_PriSideOverCurr_HW : 12|1@1+ (1,0) [0|1] ""  PC
 SG_ D2P_ALARM_PriSideOverCurr_SW : 13|1@1+ (1,0) [0|1] ""  PC
 SG_ D2P_ALARM_LowPowerSupplyErr : 14|1@1+ (1,0) [0|1] ""  PC
 SG_ D2P_ALARM_MBMUComErr : 15|1@1+ (1,0) [0|1] ""  PC
 SG_ D2P_ALARM_DCDCMsTeSaplgErr : 16|1@1+ (1,0) [0|1] ""  PC
 SG_ D2P_ALARM_DCDCTeSaplgErr : 17|1@1+ (1,0) [0|1] ""  PC
 SG_ D2P_ALARM_VoltSamplingErr : 18|1@1+ (1,0) [0|1] ""  PC
 SG_ D2P_ALARM_HgSdCuSaplgErr : 19|1@1+ (1,0) [0|1] ""  PC
 SG_ D2P_ALARM_CtrlCurrSamplingErr : 20|1@1+ (1,0) [0|1] ""  PC
 SG_ D2P_ALARM_BypassFail : 21|1@1+ (1,0) [0|1] ""  PC
 SG_ D2P_ALARM_Reserve1 : 22|1@1+ (1,0) [0|1] ""  PC
 SG_ D2P_ALARM_Reserve2 : 23|1@1+ (1,0) [0|1] ""  PC
 SG_ D2P_ALARM_Reserve3 : 24|1@1+ (1,0) [0|1] ""  PC
 SG_ D2P_ALARM_Reserve4 : 25|1@1+ (1,0) [0|1] ""  PC
 SG_ D2P_ALARM_Reserve5 : 26|1@1+ (1,0) [0|1] ""  PC
 SG_ D2P_ALARM_Reserve6 : 27|1@1+ (1,0) [0|1] ""  PC
 SG_ D2P_ALARM_Reserve7 : 28|1@1+ (1,0) [0|1] ""  PC
 SG_ D2P_ALARM_Reserve8 : 29|1@1+ (1,0) [0|1] ""  PC
 SG_ D2P_ALARM_Reserve9 : 30|1@1+ (1,0) [0|1] ""  PC
 SG_ D2P_ALARM_Reserve10 : 31|1@1+ (1,0) [0|1] ""  PC
 SG_ D2P_ALARM_Reserve11 : 32|32@1+ (1,0) [0|4294967295] ""  PC

BO_ 2149547902 D2P_ALARM__62: 8 DCDC
 SG_ D2P_ALARM_EnvExtreOverTemp : 0|1@1+ (1,0) [0|1] ""  PC
 SG_ D2P_ALARM_EnvOverTemp : 1|1@1+ (1,0) [0|1] ""  PC
 SG_ D2P_ALARM_MosOverTemp : 2|1@1+ (1,0) [0|1] ""  PC
 SG_ D2P_ALARM_MosExtreOverTemp : 3|1@1+ (1,0) [0|1] ""  PC
 SG_ D2P_ALARM_HighSideOverVolt : 4|1@1+ (1,0) [0|1] ""  PC
 SG_ D2P_ALARM_HighSideUnderVolt : 5|1@1+ (1,0) [0|1] ""  PC
 SG_ D2P_ALARM_LowSideOverVolt : 6|1@1+ (1,0) [0|1] ""  PC
 SG_ D2P_ALARM_HighSideOverCurr : 7|1@1+ (1,0) [0|1] ""  PC
 SG_ D2P_ALARM_LowSideOverCurr_HW : 8|1@1+ (1,0) [0|1] ""  PC
 SG_ D2P_ALARM_LowSideOverCurr_SW : 9|1@1+ (1,0) [0|1] ""  PC
 SG_ D2P_ALARM_SecSideOverCurr_HW : 10|1@1+ (1,0) [0|1] ""  PC
 SG_ D2P_ALARM_SecSideOverCurr_SW : 11|1@1+ (1,0) [0|1] ""  PC
 SG_ D2P_ALARM_PriSideOverCurr_HW : 12|1@1+ (1,0) [0|1] ""  PC
 SG_ D2P_ALARM_PriSideOverCurr_SW : 13|1@1+ (1,0) [0|1] ""  PC
 SG_ D2P_ALARM_LowPowerSupplyErr : 14|1@1+ (1,0) [0|1] ""  PC
 SG_ D2P_ALARM_MBMUComErr : 15|1@1+ (1,0) [0|1] ""  PC
 SG_ D2P_ALARM_DCDCMsTeSaplgErr : 16|1@1+ (1,0) [0|1] ""  PC
 SG_ D2P_ALARM_DCDCTeSaplgErr : 17|1@1+ (1,0) [0|1] ""  PC
 SG_ D2P_ALARM_VoltSamplingErr : 18|1@1+ (1,0) [0|1] ""  PC
 SG_ D2P_ALARM_HgSdCuSaplgErr : 19|1@1+ (1,0) [0|1] ""  PC
 SG_ D2P_ALARM_CtrlCurrSamplingErr : 20|1@1+ (1,0) [0|1] ""  PC
 SG_ D2P_ALARM_BypassFail : 21|1@1+ (1,0) [0|1] ""  PC
 SG_ D2P_ALARM_Reserve1 : 22|1@1+ (1,0) [0|1] ""  PC
 SG_ D2P_ALARM_Reserve2 : 23|1@1+ (1,0) [0|1] ""  PC
 SG_ D2P_ALARM_Reserve3 : 24|1@1+ (1,0) [0|1] ""  PC
 SG_ D2P_ALARM_Reserve4 : 25|1@1+ (1,0) [0|1] ""  PC
 SG_ D2P_ALARM_Reserve5 : 26|1@1+ (1,0) [0|1] ""  PC
 SG_ D2P_ALARM_Reserve6 : 27|1@1+ (1,0) [0|1] ""  PC
 SG_ D2P_ALARM_Reserve7 : 28|1@1+ (1,0) [0|1] ""  PC
 SG_ D2P_ALARM_Reserve8 : 29|1@1+ (1,0) [0|1] ""  PC
 SG_ D2P_ALARM_Reserve9 : 30|1@1+ (1,0) [0|1] ""  PC
 SG_ D2P_ALARM_Reserve10 : 31|1@1+ (1,0) [0|1] ""  PC
 SG_ D2P_ALARM_Reserve11 : 32|32@1+ (1,0) [0|4294967295] ""  PC

BO_ 2149547903 D2P_ALARM__63: 8 DCDC
 SG_ D2P_ALARM_EnvExtreOverTemp : 0|1@1+ (1,0) [0|1] ""  PC
 SG_ D2P_ALARM_EnvOverTemp : 1|1@1+ (1,0) [0|1] ""  PC
 SG_ D2P_ALARM_MosOverTemp : 2|1@1+ (1,0) [0|1] ""  PC
 SG_ D2P_ALARM_MosExtreOverTemp : 3|1@1+ (1,0) [0|1] ""  PC
 SG_ D2P_ALARM_HighSideOverVolt : 4|1@1+ (1,0) [0|1] ""  PC
 SG_ D2P_ALARM_HighSideUnderVolt : 5|1@1+ (1,0) [0|1] ""  PC
 SG_ D2P_ALARM_LowSideOverVolt : 6|1@1+ (1,0) [0|1] ""  PC
 SG_ D2P_ALARM_HighSideOverCurr : 7|1@1+ (1,0) [0|1] ""  PC
 SG_ D2P_ALARM_LowSideOverCurr_HW : 8|1@1+ (1,0) [0|1] ""  PC
 SG_ D2P_ALARM_LowSideOverCurr_SW : 9|1@1+ (1,0) [0|1] ""  PC
 SG_ D2P_ALARM_SecSideOverCurr_HW : 10|1@1+ (1,0) [0|1] ""  PC
 SG_ D2P_ALARM_SecSideOverCurr_SW : 11|1@1+ (1,0) [0|1] ""  PC
 SG_ D2P_ALARM_PriSideOverCurr_HW : 12|1@1+ (1,0) [0|1] ""  PC
 SG_ D2P_ALARM_PriSideOverCurr_SW : 13|1@1+ (1,0) [0|1] ""  PC
 SG_ D2P_ALARM_LowPowerSupplyErr : 14|1@1+ (1,0) [0|1] ""  PC
 SG_ D2P_ALARM_MBMUComErr : 15|1@1+ (1,0) [0|1] ""  PC
 SG_ D2P_ALARM_DCDCMsTeSaplgErr : 16|1@1+ (1,0) [0|1] ""  PC
 SG_ D2P_ALARM_DCDCTeSaplgErr : 17|1@1+ (1,0) [0|1] ""  PC
 SG_ D2P_ALARM_VoltSamplingErr : 18|1@1+ (1,0) [0|1] ""  PC
 SG_ D2P_ALARM_HgSdCuSaplgErr : 19|1@1+ (1,0) [0|1] ""  PC
 SG_ D2P_ALARM_CtrlCurrSamplingErr : 20|1@1+ (1,0) [0|1] ""  PC
 SG_ D2P_ALARM_BypassFail : 21|1@1+ (1,0) [0|1] ""  PC
 SG_ D2P_ALARM_Reserve1 : 22|1@1+ (1,0) [0|1] ""  PC
 SG_ D2P_ALARM_Reserve2 : 23|1@1+ (1,0) [0|1] ""  PC
 SG_ D2P_ALARM_Reserve3 : 24|1@1+ (1,0) [0|1] ""  PC
 SG_ D2P_ALARM_Reserve4 : 25|1@1+ (1,0) [0|1] ""  PC
 SG_ D2P_ALARM_Reserve5 : 26|1@1+ (1,0) [0|1] ""  PC
 SG_ D2P_ALARM_Reserve6 : 27|1@1+ (1,0) [0|1] ""  PC
 SG_ D2P_ALARM_Reserve7 : 28|1@1+ (1,0) [0|1] ""  PC
 SG_ D2P_ALARM_Reserve8 : 29|1@1+ (1,0) [0|1] ""  PC
 SG_ D2P_ALARM_Reserve9 : 30|1@1+ (1,0) [0|1] ""  PC
 SG_ D2P_ALARM_Reserve10 : 31|1@1+ (1,0) [0|1] ""  PC
 SG_ D2P_ALARM_Reserve11 : 32|32@1+ (1,0) [0|4294967295] ""  PC

BO_ 2334457665 S2A_SUMDATA10__01: 8 SBMU
 SG_ Reserve : 0|32@1+ (0.1,0) [0|429496729.5] "%"  PC
 SG_ S2A_BAT_I_HVS_mA_01 : 32|32@1+ (1,-2000000) [-2000000|4292967295] "mA"  PC

BO_ 2334457666 S2A_SUMDATA10__02: 8 SBMU
 SG_ Reserve : 0|32@1+ (0.1,0) [0|429496729.5] "%"  PC
 SG_ S2A_BAT_I_HVS_mA_02 : 32|32@1+ (1,-2000000) [-2000000|4292967295] "mA"  PC

BO_ 2334457667 S2A_SUMDATA10__03: 8 SBMU
 SG_ Reserve : 0|32@1+ (0.1,0) [0|429496729.5] "%"  PC
 SG_ S2A_BAT_I_HVS_mA_03 : 32|32@1+ (1,-2000000) [-2000000|4292967295] "mA"  PC

BO_ 2334457668 S2A_SUMDATA10__04: 8 SBMU
 SG_ Reserve : 0|32@1+ (0.1,0) [0|429496729.5] "%"  PC
 SG_ S2A_BAT_I_HVS_mA_04 : 32|32@1+ (1,-2000000) [-2000000|4292967295] "mA"  PC

BO_ 2334457669 S2A_SUMDATA10__05: 8 SBMU
 SG_ Reserve : 0|32@1+ (0.1,0) [0|429496729.5] "%"  PC
 SG_ S2A_BAT_I_HVS_mA_05 : 32|32@1+ (1,-2000000) [-2000000|4292967295] "mA"  PC

BO_ 2334457670 S2A_SUMDATA10__06: 8 SBMU
 SG_ Reserve : 0|32@1+ (0.1,0) [0|429496729.5] "%"  PC
 SG_ S2A_BAT_I_HVS_mA_06 : 32|32@1+ (1,-2000000) [-2000000|4292967295] "mA"  PC

BO_ 2334457671 S2A_SUMDATA10__07: 8 SBMU
 SG_ Reserve : 0|32@1+ (0.1,0) [0|429496729.5] "%"  PC
 SG_ S2A_BAT_I_HVS_mA_07 : 32|32@1+ (1,-2000000) [-2000000|4292967295] "mA"  PC

BO_ 2334457672 S2A_SUMDATA10__08: 8 SBMU
 SG_ Reserve : 0|32@1+ (0.1,0) [0|429496729.5] "%"  PC
 SG_ S2A_BAT_I_HVS_mA_08 : 32|32@1+ (1,-2000000) [-2000000|4292967295] "mA"  PC

BO_ 2334457673 S2A_SUMDATA10__09: 8 SBMU
 SG_ Reserve : 0|32@1+ (0.1,0) [0|429496729.5] "%"  PC
 SG_ S2A_BAT_I_HVS_mA_09 : 32|32@1+ (1,-2000000) [-2000000|4292967295] "mA"  PC

BO_ 2334457674 S2A_SUMDATA10__10: 8 SBMU
 SG_ Reserve : 0|32@1+ (0.1,0) [0|429496729.5] "%"  PC
 SG_ S2A_BAT_I_HVS_mA_10 : 32|32@1+ (1,-2000000) [-2000000|4292967295] "mA"  PC

BO_ 2334457675 S2A_SUMDATA10__11: 8 SBMU
 SG_ Reserve : 0|32@1+ (0.1,0) [0|429496729.5] "%"  PC
 SG_ S2A_BAT_I_HVS_mA_11 : 32|32@1+ (1,-2000000) [-2000000|4292967295] "mA"  PC

BO_ 2334457676 S2A_SUMDATA10__12: 8 SBMU
 SG_ Reserve : 0|32@1+ (0.1,0) [0|429496729.5] "%"  PC
 SG_ S2A_BAT_I_HVS_mA_12 : 32|32@1+ (1,-2000000) [-2000000|4292967295] "mA"  PC

BO_ 2334457677 S2A_SUMDATA10__13: 8 SBMU
 SG_ Reserve : 0|32@1+ (0.1,0) [0|429496729.5] "%"  PC
 SG_ S2A_BAT_I_HVS_mA_13 : 32|32@1+ (1,-2000000) [-2000000|4292967295] "mA"  PC

BO_ 2334457678 S2A_SUMDATA10__14: 8 SBMU
 SG_ Reserve : 0|32@1+ (0.1,0) [0|429496729.5] "%"  PC
 SG_ S2A_BAT_I_HVS_mA_14 : 32|32@1+ (1,-2000000) [-2000000|4292967295] "mA"  PC

BO_ 2334457679 S2A_SUMDATA10__15: 8 SBMU
 SG_ Reserve : 0|32@1+ (0.1,0) [0|429496729.5] "%"  PC
 SG_ S2A_BAT_I_HVS_mA_15 : 32|32@1+ (1,-2000000) [-2000000|4292967295] "mA"  PC

BO_ 2334457680 S2A_SUMDATA10__16: 8 SBMU
 SG_ Reserve : 0|32@1+ (0.1,0) [0|429496729.5] "%"  PC
 SG_ S2A_BAT_I_HVS_mA_16 : 32|32@1+ (1,-2000000) [-2000000|4292967295] "mA"  PC

BO_ 2334457681 S2A_SUMDATA10__17: 8 SBMU
 SG_ Reserve : 0|32@1+ (0.1,0) [0|429496729.5] "%"  PC
 SG_ S2A_BAT_I_HVS_mA_17 : 32|32@1+ (1,-2000000) [-2000000|4292967295] "mA"  PC

BO_ 2334457682 S2A_SUMDATA10__18: 8 SBMU
 SG_ Reserve : 0|32@1+ (0.1,0) [0|429496729.5] "%"  PC
 SG_ S2A_BAT_I_HVS_mA_18 : 32|32@1+ (1,-2000000) [-2000000|4292967295] "mA"  PC

BO_ 2334457683 S2A_SUMDATA10__19: 8 SBMU
 SG_ Reserve : 0|32@1+ (0.1,0) [0|429496729.5] "%"  PC
 SG_ S2A_BAT_I_HVS_mA_19 : 32|32@1+ (1,-2000000) [-2000000|4292967295] "mA"  PC

BO_ 2334457684 S2A_SUMDATA10__20: 8 SBMU
 SG_ Reserve : 0|32@1+ (0.1,0) [0|429496729.5] "%"  PC
 SG_ S2A_BAT_I_HVS_mA_20 : 32|32@1+ (1,-2000000) [-2000000|4292967295] "mA"  PC

BO_ 2334457685 S2A_SUMDATA10__21: 8 SBMU
 SG_ Reserve : 0|32@1+ (0.1,0) [0|429496729.5] "%"  PC
 SG_ S2A_BAT_I_HVS_mA_21 : 32|32@1+ (1,-2000000) [-2000000|4292967295] "mA"  PC

BO_ 2334457686 S2A_SUMDATA10__22: 8 SBMU
 SG_ Reserve : 0|32@1+ (0.1,0) [0|429496729.5] "%"  PC
 SG_ S2A_BAT_I_HVS_mA_22 : 32|32@1+ (1,-2000000) [-2000000|4292967295] "mA"  PC

BO_ 2334457687 S2A_SUMDATA10__23: 8 SBMU
 SG_ Reserve : 0|32@1+ (0.1,0) [0|429496729.5] "%"  PC
 SG_ S2A_BAT_I_HVS_mA_23 : 32|32@1+ (1,-2000000) [-2000000|4292967295] "mA"  PC

BO_ 2334457688 S2A_SUMDATA10__24: 8 SBMU
 SG_ Reserve : 0|32@1+ (0.1,0) [0|429496729.5] "%"  PC
 SG_ S2A_BAT_I_HVS_mA_24 : 32|32@1+ (1,-2000000) [-2000000|4292967295] "mA"  PC

BO_ 2334457689 S2A_SUMDATA10__25: 8 SBMU
 SG_ Reserve : 0|32@1+ (0.1,0) [0|429496729.5] "%"  PC
 SG_ S2A_BAT_I_HVS_mA_25 : 32|32@1+ (1,-2000000) [-2000000|4292967295] "mA"  PC

BO_ 2334457690 S2A_SUMDATA10__26: 8 SBMU
 SG_ Reserve : 0|32@1+ (0.1,0) [0|429496729.5] "%"  PC
 SG_ S2A_BAT_I_HVS_mA_26 : 32|32@1+ (1,-2000000) [-2000000|4292967295] "mA"  PC

BO_ 2334457691 S2A_SUMDATA10__27: 8 SBMU
 SG_ Reserve : 0|32@1+ (0.1,0) [0|429496729.5] "%"  PC
 SG_ S2A_BAT_I_HVS_mA_27 : 32|32@1+ (1,-2000000) [-2000000|4292967295] "mA"  PC

BO_ 2334457692 S2A_SUMDATA10__28: 8 SBMU
 SG_ Reserve : 0|32@1+ (0.1,0) [0|429496729.5] "%"  PC
 SG_ S2A_BAT_I_HVS_mA_28 : 32|32@1+ (1,-2000000) [-2000000|4292967295] "mA"  PC

BO_ 2334457693 S2A_SUMDATA10__29: 8 SBMU
 SG_ Reserve : 0|32@1+ (0.1,0) [0|429496729.5] "%"  PC
 SG_ S2A_BAT_I_HVS_mA_29 : 32|32@1+ (1,-2000000) [-2000000|4292967295] "mA"  PC

BO_ 2334457694 S2A_SUMDATA10__30: 8 SBMU
 SG_ Reserve : 0|32@1+ (0.1,0) [0|429496729.5] "%"  PC
 SG_ S2A_BAT_I_HVS_mA_30 : 32|32@1+ (1,-2000000) [-2000000|4292967295] "mA"  PC

BO_ 2334457695 S2A_SUMDATA10__31: 8 SBMU
 SG_ Reserve : 0|32@1+ (0.1,0) [0|429496729.5] "%"  PC
 SG_ S2A_BAT_I_HVS_mA_31 : 32|32@1+ (1,-2000000) [-2000000|4292967295] "mA"  PC

BO_ 2334457696 S2A_SUMDATA10__32: 8 SBMU
 SG_ Reserve : 0|32@1+ (0.1,0) [0|429496729.5] "%"  PC
 SG_ S2A_BAT_I_HVS_mA_32 : 32|32@1+ (1,-2000000) [-2000000|4292967295] "mA"  PC

BO_ 2334457697 S2A_SUMDATA10__33: 8 SBMU
 SG_ Reserve : 0|32@1+ (0.1,0) [0|429496729.5] "%"  PC
 SG_ S2A_BAT_I_HVS_mA_33 : 32|32@1+ (1,-2000000) [-2000000|4292967295] "mA"  PC

BO_ 2334457698 S2A_SUMDATA10__34: 8 SBMU
 SG_ Reserve : 0|32@1+ (0.1,0) [0|429496729.5] "%"  PC
 SG_ S2A_BAT_I_HVS_mA_34 : 32|32@1+ (1,-2000000) [-2000000|4292967295] "mA"  PC

BO_ 2334457699 S2A_SUMDATA10__35: 8 SBMU
 SG_ Reserve : 0|32@1+ (0.1,0) [0|429496729.5] "%"  PC
 SG_ S2A_BAT_I_HVS_mA_35 : 32|32@1+ (1,-2000000) [-2000000|4292967295] "mA"  PC

BO_ 2334457700 S2A_SUMDATA10__36: 8 SBMU
 SG_ Reserve : 0|32@1+ (0.1,0) [0|429496729.5] "%"  PC
 SG_ S2A_BAT_I_HVS_mA_36 : 32|32@1+ (1,-2000000) [-2000000|4292967295] "mA"  PC

BO_ 2334457701 S2A_SUMDATA10__37: 8 SBMU
 SG_ Reserve : 0|32@1+ (0.1,0) [0|429496729.5] "%"  PC
 SG_ S2A_BAT_I_HVS_mA_37 : 32|32@1+ (1,-2000000) [-2000000|4292967295] "mA"  PC

BO_ 2334457702 S2A_SUMDATA10__38: 8 SBMU
 SG_ Reserve : 0|32@1+ (0.1,0) [0|429496729.5] "%"  PC
 SG_ S2A_BAT_I_HVS_mA_38 : 32|32@1+ (1,-2000000) [-2000000|4292967295] "mA"  PC

BO_ 2334457703 S2A_SUMDATA10__39: 8 SBMU
 SG_ Reserve : 0|32@1+ (0.1,0) [0|429496729.5] "%"  PC
 SG_ S2A_BAT_I_HVS_mA_39 : 32|32@1+ (1,-2000000) [-2000000|4292967295] "mA"  PC

BO_ 2334457704 S2A_SUMDATA10__40: 8 SBMU
 SG_ Reserve : 0|32@1+ (0.1,0) [0|429496729.5] "%"  PC
 SG_ S2A_BAT_I_HVS_mA_40 : 32|32@1+ (1,-2000000) [-2000000|4292967295] "mA"  PC

BO_ 2334457705 S2A_SUMDATA10__41: 8 SBMU
 SG_ Reserve : 0|32@1+ (0.1,0) [0|429496729.5] "%"  PC
 SG_ S2A_BAT_I_HVS_mA_41 : 32|32@1+ (1,-2000000) [-2000000|4292967295] "mA"  PC

BO_ 2334457706 S2A_SUMDATA10__42: 8 SBMU
 SG_ Reserve : 0|32@1+ (0.1,0) [0|429496729.5] "%"  PC
 SG_ S2A_BAT_I_HVS_mA_42 : 32|32@1+ (1,-2000000) [-2000000|4292967295] "mA"  PC

BO_ 2334457707 S2A_SUMDATA10__43: 8 SBMU
 SG_ Reserve : 0|32@1+ (0.1,0) [0|429496729.5] "%"  PC
 SG_ S2A_BAT_I_HVS_mA_43 : 32|32@1+ (1,-2000000) [-2000000|4292967295] "mA"  PC

BO_ 2334457708 S2A_SUMDATA10__44: 8 SBMU
 SG_ Reserve : 0|32@1+ (0.1,0) [0|429496729.5] "%"  PC
 SG_ S2A_BAT_I_HVS_mA_44 : 32|32@1+ (1,-2000000) [-2000000|4292967295] "mA"  PC

BO_ 2334457709 S2A_SUMDATA10__45: 8 SBMU
 SG_ Reserve : 0|32@1+ (0.1,0) [0|429496729.5] "%"  PC
 SG_ S2A_BAT_I_HVS_mA_45 : 32|32@1+ (1,-2000000) [-2000000|4292967295] "mA"  PC

BO_ 2334457710 S2A_SUMDATA10__46: 8 SBMU
 SG_ Reserve : 0|32@1+ (0.1,0) [0|429496729.5] "%"  PC
 SG_ S2A_BAT_I_HVS_mA_46 : 32|32@1+ (1,-2000000) [-2000000|4292967295] "mA"  PC

BO_ 2334457711 S2A_SUMDATA10__47: 8 SBMU
 SG_ Reserve : 0|32@1+ (0.1,0) [0|429496729.5] "%"  PC
 SG_ S2A_BAT_I_HVS_mA_47 : 32|32@1+ (1,-2000000) [-2000000|4292967295] "mA"  PC

BO_ 2334457712 S2A_SUMDATA10__48: 8 SBMU
 SG_ Reserve : 0|32@1+ (0.1,0) [0|429496729.5] "%"  PC
 SG_ S2A_BAT_I_HVS_mA_48 : 32|32@1+ (1,-2000000) [-2000000|4292967295] "mA"  PC

BO_ 2334457713 S2A_SUMDATA10__49: 8 SBMU
 SG_ Reserve : 0|32@1+ (0.1,0) [0|429496729.5] "%"  PC
 SG_ S2A_BAT_I_HVS_mA_49 : 32|32@1+ (1,-2000000) [-2000000|4292967295] "mA"  PC

BO_ 2334457714 S2A_SUMDATA10__50: 8 SBMU
 SG_ Reserve : 0|32@1+ (0.1,0) [0|429496729.5] "%"  PC
 SG_ S2A_BAT_I_HVS_mA_50 : 32|32@1+ (1,-2000000) [-2000000|4292967295] "mA"  PC

BO_ 2334457715 S2A_SUMDATA10__51: 8 SBMU
 SG_ Reserve : 0|32@1+ (0.1,0) [0|429496729.5] "%"  PC
 SG_ S2A_BAT_I_HVS_mA_51 : 32|32@1+ (1,-2000000) [-2000000|4292967295] "mA"  PC

BO_ 2334457716 S2A_SUMDATA10__52: 8 SBMU
 SG_ Reserve : 0|32@1+ (0.1,0) [0|429496729.5] "%"  PC
 SG_ S2A_BAT_I_HVS_mA_52 : 32|32@1+ (1,-2000000) [-2000000|4292967295] "mA"  PC

BO_ 2334457717 S2A_SUMDATA10__53: 8 SBMU
 SG_ Reserve : 0|32@1+ (0.1,0) [0|429496729.5] "%"  PC
 SG_ S2A_BAT_I_HVS_mA_53 : 32|32@1+ (1,-2000000) [-2000000|4292967295] "mA"  PC

BO_ 2334457718 S2A_SUMDATA10__54: 8 SBMU
 SG_ Reserve : 0|32@1+ (0.1,0) [0|429496729.5] "%"  PC
 SG_ S2A_BAT_I_HVS_mA_54 : 32|32@1+ (1,-2000000) [-2000000|4292967295] "mA"  PC

BO_ 2334457719 S2A_SUMDATA10__55: 8 SBMU
 SG_ Reserve : 0|32@1+ (0.1,0) [0|429496729.5] "%"  PC
 SG_ S2A_BAT_I_HVS_mA_55 : 32|32@1+ (1,-2000000) [-2000000|4292967295] "mA"  PC

BO_ 2334457720 S2A_SUMDATA10__56: 8 SBMU
 SG_ Reserve : 0|32@1+ (0.1,0) [0|429496729.5] "%"  PC
 SG_ S2A_BAT_I_HVS_mA_56 : 32|32@1+ (1,-2000000) [-2000000|4292967295] "mA"  PC

BO_ 2334457721 S2A_SUMDATA10__57: 8 SBMU
 SG_ Reserve : 0|32@1+ (0.1,0) [0|429496729.5] "%"  PC
 SG_ S2A_BAT_I_HVS_mA_57 : 32|32@1+ (1,-2000000) [-2000000|4292967295] "mA"  PC

BO_ 2334457722 S2A_SUMDATA10__58: 8 SBMU
 SG_ Reserve : 0|32@1+ (0.1,0) [0|429496729.5] "%"  PC
 SG_ S2A_BAT_I_HVS_mA_58 : 32|32@1+ (1,-2000000) [-2000000|4292967295] "mA"  PC

BO_ 2334457723 S2A_SUMDATA10__59: 8 SBMU
 SG_ Reserve : 0|32@1+ (0.1,0) [0|429496729.5] "%"  PC
 SG_ S2A_BAT_I_HVS_mA_59 : 32|32@1+ (1,-2000000) [-2000000|4292967295] "mA"  PC

BO_ 2334457724 S2A_SUMDATA10__60: 8 SBMU
 SG_ Reserve : 0|32@1+ (0.1,0) [0|429496729.5] "%"  PC
 SG_ S2A_BAT_I_HVS_mA_60 : 32|32@1+ (1,-2000000) [-2000000|4292967295] "mA"  PC

BO_ 2334457725 S2A_SUMDATA10__61: 8 SBMU
 SG_ Reserve : 0|32@1+ (0.1,0) [0|429496729.5] "%"  PC
 SG_ S2A_BAT_I_HVS_mA_61 : 32|32@1+ (1,-2000000) [-2000000|4292967295] "mA"  PC

BO_ 2334457726 S2A_SUMDATA10__62: 8 SBMU
 SG_ Reserve : 0|32@1+ (0.1,0) [0|429496729.5] "%"  PC
 SG_ S2A_BAT_I_HVS_mA_62 : 32|32@1+ (1,-2000000) [-2000000|4292967295] "mA"  PC

BO_ 2334457727 S2A_SUMDATA10__63: 8 SBMU
 SG_ Reserve : 0|32@1+ (0.1,0) [0|429496729.5] "%"  PC
 SG_ S2A_BAT_I_HVS_mA_63 : 32|32@1+ (1,-2000000) [-2000000|4292967295] "mA"  PC

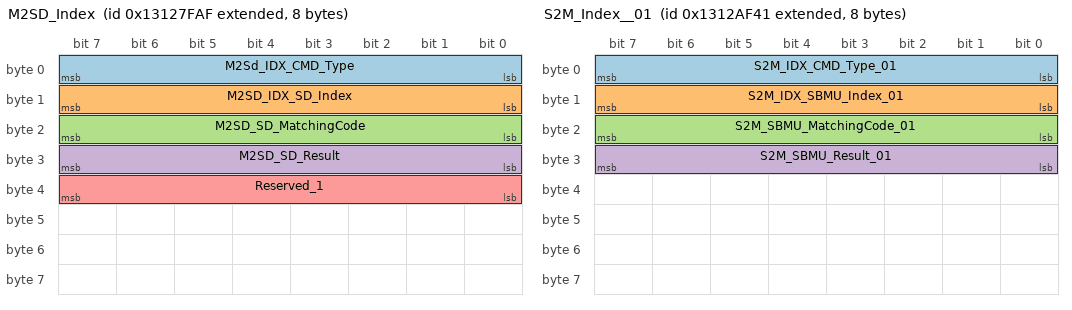
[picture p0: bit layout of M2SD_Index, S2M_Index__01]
BO_ 2467463087 M2SD_Index: 8 MBMU
 SG_ M2Sd_IDX_CMD_Type : 0|8@1+ (1,0) [0|255] ""  SBMU,DCDC
 SG_ M2SD_IDX_SD_Index : 8|8@1+ (1,0) [0|255] ""  SBMU,DCDC
 SG_ M2SD_SD_MatchingCode : 16|8@1+ (1,0) [0|255] ""  SBMU,DCDC
 SG_ M2SD_SD_Result : 24|8@1+ (1,0) [0|255] ""  SBMU,DCDC
 SG_ Reserved_1 : 32|8@1+ (1,0) [0|255] ""  SBMU,DCDC

BO_ 2467475265 S2M_Index__01: 8 SBMU
 SG_ S2M_IDX_CMD_Type_01 : 0|8@1+ (1,0) [0|255] ""  MBMU
 SG_ S2M_IDX_SBMU_Index_01 : 8|8@1+ (1,0) [0|255] ""  MBMU
 SG_ S2M_SBMU_MatchingCode_01 : 16|8@1+ (1,0) [0|255] ""  MBMU
 SG_ S2M_SBMU_Result_01 : 24|8@1+ (1,0) [0|255] ""  MBMU

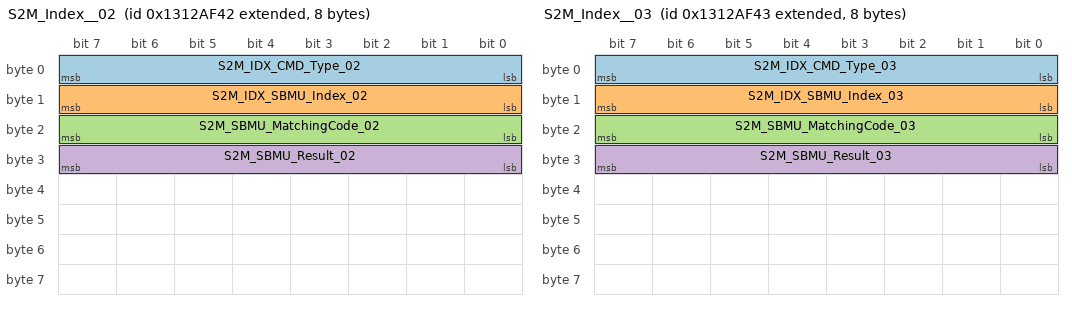
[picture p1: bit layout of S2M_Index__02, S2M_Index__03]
BO_ 2467475266 S2M_Index__02: 8 SBMU
 SG_ S2M_IDX_CMD_Type_02 : 0|8@1+ (1,0) [0|255] ""  MBMU
 SG_ S2M_IDX_SBMU_Index_02 : 8|8@1+ (1,0) [0|255] ""  MBMU
 SG_ S2M_SBMU_MatchingCode_02 : 16|8@1+ (1,0) [0|255] ""  MBMU
 SG_ S2M_SBMU_Result_02 : 24|8@1+ (1,0) [0|255] ""  MBMU

BO_ 2467475267 S2M_Index__03: 8 SBMU
 SG_ S2M_IDX_CMD_Type_03 : 0|8@1+ (1,0) [0|255] ""  MBMU
 SG_ S2M_IDX_SBMU_Index_03 : 8|8@1+ (1,0) [0|255] ""  MBMU
 SG_ S2M_SBMU_MatchingCode_03 : 16|8@1+ (1,0) [0|255] ""  MBMU
 SG_ S2M_SBMU_Result_03 : 24|8@1+ (1,0) [0|255] ""  MBMU

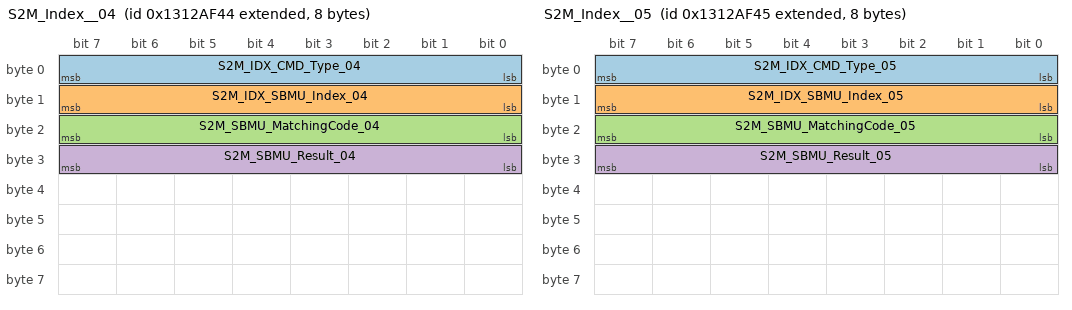
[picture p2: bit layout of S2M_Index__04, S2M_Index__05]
BO_ 2467475268 S2M_Index__04: 8 SBMU
 SG_ S2M_IDX_CMD_Type_04 : 0|8@1+ (1,0) [0|255] ""  MBMU
 SG_ S2M_IDX_SBMU_Index_04 : 8|8@1+ (1,0) [0|255] ""  MBMU
 SG_ S2M_SBMU_MatchingCode_04 : 16|8@1+ (1,0) [0|255] ""  MBMU
 SG_ S2M_SBMU_Result_04 : 24|8@1+ (1,0) [0|255] ""  MBMU

BO_ 2467475269 S2M_Index__05: 8 SBMU
 SG_ S2M_IDX_CMD_Type_05 : 0|8@1+ (1,0) [0|255] ""  MBMU
 SG_ S2M_IDX_SBMU_Index_05 : 8|8@1+ (1,0) [0|255] ""  MBMU
 SG_ S2M_SBMU_MatchingCode_05 : 16|8@1+ (1,0) [0|255] ""  MBMU
 SG_ S2M_SBMU_Result_05 : 24|8@1+ (1,0) [0|255] ""  MBMU

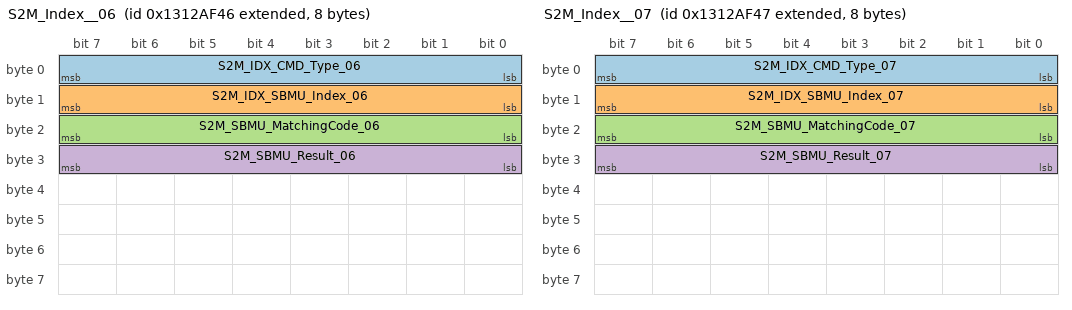
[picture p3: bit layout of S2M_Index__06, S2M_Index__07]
BO_ 2467475270 S2M_Index__06: 8 SBMU
 SG_ S2M_IDX_CMD_Type_06 : 0|8@1+ (1,0) [0|255] ""  MBMU
 SG_ S2M_IDX_SBMU_Index_06 : 8|8@1+ (1,0) [0|255] ""  MBMU
 SG_ S2M_SBMU_MatchingCode_06 : 16|8@1+ (1,0) [0|255] ""  MBMU
 SG_ S2M_SBMU_Result_06 : 24|8@1+ (1,0) [0|255] ""  MBMU

BO_ 2467475271 S2M_Index__07: 8 SBMU
 SG_ S2M_IDX_CMD_Type_07 : 0|8@1+ (1,0) [0|255] ""  MBMU
 SG_ S2M_IDX_SBMU_Index_07 : 8|8@1+ (1,0) [0|255] ""  MBMU
 SG_ S2M_SBMU_MatchingCode_07 : 16|8@1+ (1,0) [0|255] ""  MBMU
 SG_ S2M_SBMU_Result_07 : 24|8@1+ (1,0) [0|255] ""  MBMU

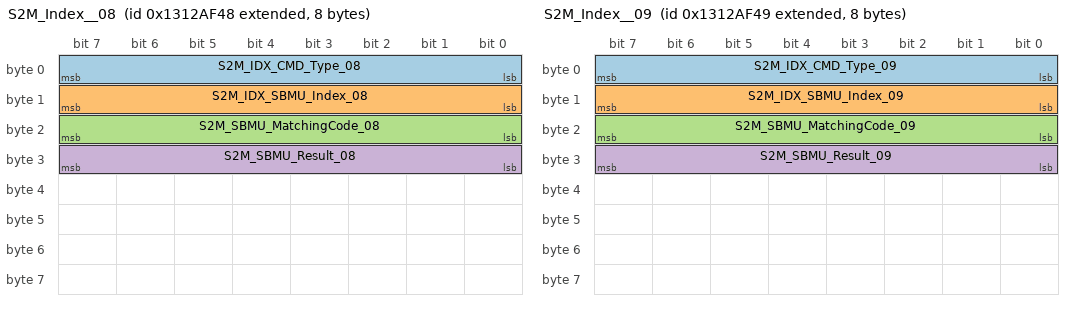
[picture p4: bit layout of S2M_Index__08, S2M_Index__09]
BO_ 2467475272 S2M_Index__08: 8 SBMU
 SG_ S2M_IDX_CMD_Type_08 : 0|8@1+ (1,0) [0|255] ""  MBMU
 SG_ S2M_IDX_SBMU_Index_08 : 8|8@1+ (1,0) [0|255] ""  MBMU
 SG_ S2M_SBMU_MatchingCode_08 : 16|8@1+ (1,0) [0|255] ""  MBMU
 SG_ S2M_SBMU_Result_08 : 24|8@1+ (1,0) [0|255] ""  MBMU

BO_ 2467475273 S2M_Index__09: 8 SBMU
 SG_ S2M_IDX_CMD_Type_09 : 0|8@1+ (1,0) [0|255] ""  MBMU
 SG_ S2M_IDX_SBMU_Index_09 : 8|8@1+ (1,0) [0|255] ""  MBMU
 SG_ S2M_SBMU_MatchingCode_09 : 16|8@1+ (1,0) [0|255] ""  MBMU
 SG_ S2M_SBMU_Result_09 : 24|8@1+ (1,0) [0|255] ""  MBMU

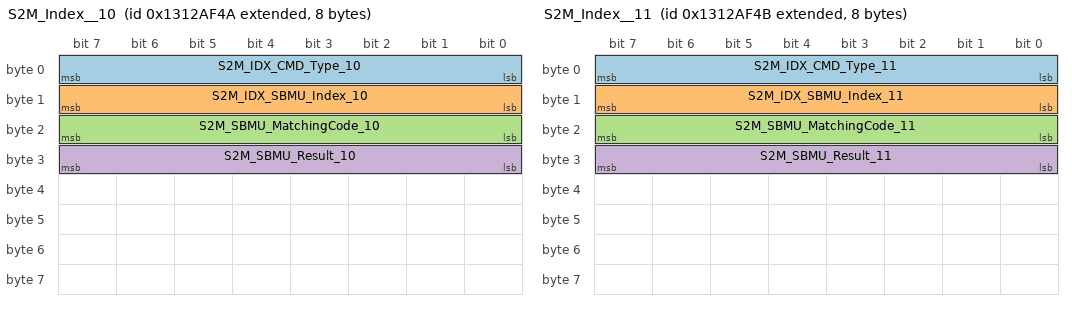
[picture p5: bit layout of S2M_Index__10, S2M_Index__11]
BO_ 2467475274 S2M_Index__10: 8 SBMU
 SG_ S2M_IDX_CMD_Type_10 : 0|8@1+ (1,0) [0|255] ""  MBMU
 SG_ S2M_IDX_SBMU_Index_10 : 8|8@1+ (1,0) [0|255] ""  MBMU
 SG_ S2M_SBMU_MatchingCode_10 : 16|8@1+ (1,0) [0|255] ""  MBMU
 SG_ S2M_SBMU_Result_10 : 24|8@1+ (1,0) [0|255] ""  MBMU

BO_ 2467475275 S2M_Index__11: 8 SBMU
 SG_ S2M_IDX_CMD_Type_11 : 0|8@1+ (1,0) [0|255] ""  MBMU
 SG_ S2M_IDX_SBMU_Index_11 : 8|8@1+ (1,0) [0|255] ""  MBMU
 SG_ S2M_SBMU_MatchingCode_11 : 16|8@1+ (1,0) [0|255] ""  MBMU
 SG_ S2M_SBMU_Result_11 : 24|8@1+ (1,0) [0|255] ""  MBMU

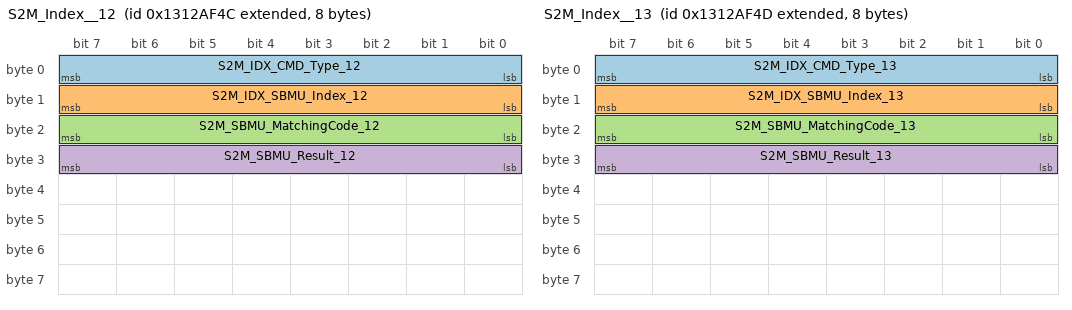
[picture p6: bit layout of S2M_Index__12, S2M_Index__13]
BO_ 2467475276 S2M_Index__12: 8 SBMU
 SG_ S2M_IDX_CMD_Type_12 : 0|8@1+ (1,0) [0|255] ""  MBMU
 SG_ S2M_IDX_SBMU_Index_12 : 8|8@1+ (1,0) [0|255] ""  MBMU
 SG_ S2M_SBMU_MatchingCode_12 : 16|8@1+ (1,0) [0|255] ""  MBMU
 SG_ S2M_SBMU_Result_12 : 24|8@1+ (1,0) [0|255] ""  MBMU

BO_ 2467475277 S2M_Index__13: 8 SBMU
 SG_ S2M_IDX_CMD_Type_13 : 0|8@1+ (1,0) [0|255] ""  MBMU
 SG_ S2M_IDX_SBMU_Index_13 : 8|8@1+ (1,0) [0|255] ""  MBMU
 SG_ S2M_SBMU_MatchingCode_13 : 16|8@1+ (1,0) [0|255] ""  MBMU
 SG_ S2M_SBMU_Result_13 : 24|8@1+ (1,0) [0|255] ""  MBMU

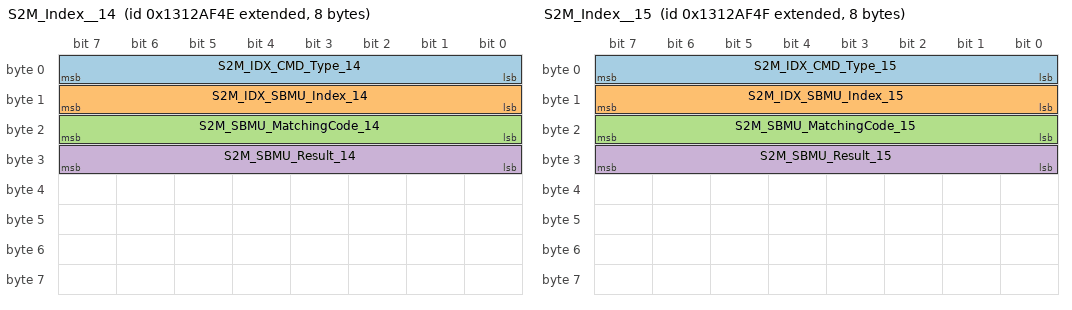
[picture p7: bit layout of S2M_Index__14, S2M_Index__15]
BO_ 2467475278 S2M_Index__14: 8 SBMU
 SG_ S2M_IDX_CMD_Type_14 : 0|8@1+ (1,0) [0|255] ""  MBMU
 SG_ S2M_IDX_SBMU_Index_14 : 8|8@1+ (1,0) [0|255] ""  MBMU
 SG_ S2M_SBMU_MatchingCode_14 : 16|8@1+ (1,0) [0|255] ""  MBMU
 SG_ S2M_SBMU_Result_14 : 24|8@1+ (1,0) [0|255] ""  MBMU

BO_ 2467475279 S2M_Index__15: 8 SBMU
 SG_ S2M_IDX_CMD_Type_15 : 0|8@1+ (1,0) [0|255] ""  MBMU
 SG_ S2M_IDX_SBMU_Index_15 : 8|8@1+ (1,0) [0|255] ""  MBMU
 SG_ S2M_SBMU_MatchingCode_15 : 16|8@1+ (1,0) [0|255] ""  MBMU
 SG_ S2M_SBMU_Result_15 : 24|8@1+ (1,0) [0|255] ""  MBMU

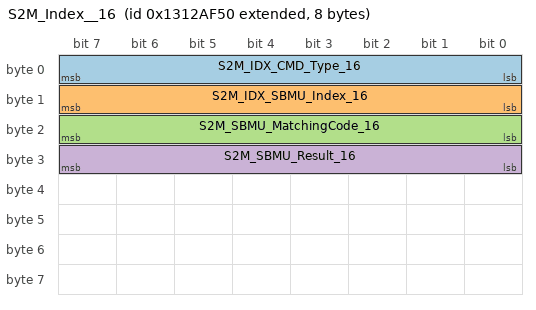
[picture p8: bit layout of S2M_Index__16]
BO_ 2467475280 S2M_Index__16: 8 SBMU
 SG_ S2M_IDX_CMD_Type_16 : 0|8@1+ (1,0) [0|255] ""  MBMU
 SG_ S2M_IDX_SBMU_Index_16 : 8|8@1+ (1,0) [0|255] ""  MBMU
 SG_ S2M_SBMU_MatchingCode_16 : 16|8@1+ (1,0) [0|255] ""  MBMU
 SG_ S2M_SBMU_Result_16 : 24|8@1+ (1,0) [0|255] ""  MBMU

CM_ SG_ 2149547879 D2P_ALARM_EnvExtreOverTemp "环境极限过温";
CM_ SG_ 2149547879 D2P_ALARM_EnvOverTemp "环境过温";
CM_ SG_ 2149547879 D2P_ALARM_MosOverTemp "MOS管过温";
CM_ SG_ 2149547879 D2P_ALARM_MosExtreOverTemp "MOS管极限过温";
CM_ SG_ 2149547879 D2P_ALARM_HighSideOverVolt "高压侧过压故障";
CM_ SG_ 2149547879 D2P_ALARM_HighSideUnderVolt "高压侧欠压故障";
CM_ SG_ 2149547879 D2P_ALARM_LowSideOverVolt "低压侧过压故障";
CM_ SG_ 2149547879 D2P_ALARM_HighSideOverCurr "高压侧过流故障";
CM_ SG_ 2149547879 D2P_ALARM_LowSideOverCurr_HW "低压侧硬件过流故障";
CM_ SG_ 2149547879 D2P_ALARM_LowSideOverCurr_SW "低压侧软件过流故障";
CM_ SG_ 2149547879 D2P_ALARM_SecSideOverCurr_HW "谐振腔副边硬件过流";
CM_ SG_ 2149547879 D2P_ALARM_SecSideOverCurr_SW "谐振腔副边软件过流";
CM_ SG_ 2149547879 D2P_ALARM_PriSideOverCurr_HW "谐振腔源边硬件过流";
CM_ SG_ 2149547879 D2P_ALARM_PriSideOverCurr_SW "谐振腔源边软件过流";
CM_ SG_ 2149547879 D2P_ALARM_LowPowerSupplyErr "低压电源供电异常";
CM_ SG_ 2149547879 D2P_ALARM_MBMUComErr "MBMU通讯故障";
CM_ SG_ 2149547879 D2P_ALARM_DCDCMsTeSaplgErr "DCDCMOS管采样温度异常（单点）";
CM_ SG_ 2149547879 D2P_ALARM_DCDCTeSaplgErr "DCDC温度采样异常（双点及以上)";
CM_ SG_ 2149547879 D2P_ALARM_VoltSamplingErr "电压采样异常";
CM_ SG_ 2149547879 D2P_ALARM_HgSdCuSaplgErr "高压侧电流采样异常";
CM_ SG_ 2149547879 D2P_ALARM_CtrlCurrSamplingErr "控制电流采样异常";
CM_ SG_ 2149547879 D2P_ALARM_BypassFail "切旁路失败";
CM_ SG_ 2149547879 D2P_ALARM_Reserve1 "预留数据";
CM_ SG_ 2149547879 D2P_ALARM_Reserve2 "预留数据";
CM_ SG_ 2149547879 D2P_ALARM_Reserve3 "预留数据";
CM_ SG_ 2149547879 D2P_ALARM_Reserve4 "预留数据";
CM_ SG_ 2149547879 D2P_ALARM_Reserve5 "预留数据";
CM_ SG_ 2149547879 D2P_ALARM_Reserve6 "预留数据";
CM_ SG_ 2149547879 D2P_ALARM_Reserve7 "预留数据";
CM_ SG_ 2149547879 D2P_ALARM_Reserve8 "预留数据";
CM_ SG_ 2149547879 D2P_ALARM_Reserve9 "预留数据";
CM_ SG_ 2149547879 D2P_ALARM_Reserve10 "预留数据";
CM_ SG_ 2149547879 D2P_ALARM_Reserve11 "预留数据";
CM_ SG_ 2149547880 D2P_ALARM_EnvExtreOverTemp "环境极限过温";
CM_ SG_ 2149547880 D2P_ALARM_EnvOverTemp "环境过温";
CM_ SG_ 2149547880 D2P_ALARM_MosOverTemp "MOS管过温";
CM_ SG_ 2149547880 D2P_ALARM_MosExtreOverTemp "MOS管极限过温";
CM_ SG_ 2149547880 D2P_ALARM_HighSideOverVolt "高压侧过压故障";
CM_ SG_ 2149547880 D2P_ALARM_HighSideUnderVolt "高压侧欠压故障";
CM_ SG_ 2149547880 D2P_ALARM_LowSideOverVolt "低压侧过压故障";
CM_ SG_ 2149547880 D2P_ALARM_HighSideOverCurr "高压侧过流故障";
CM_ SG_ 2149547880 D2P_ALARM_LowSideOverCurr_HW "低压侧硬件过流故障";
CM_ SG_ 2149547880 D2P_ALARM_LowSideOverCurr_SW "低压侧软件过流故障";
CM_ SG_ 2149547880 D2P_ALARM_SecSideOverCurr_HW "谐振腔副边硬件过流";
CM_ SG_ 2149547880 D2P_ALARM_SecSideOverCurr_SW "谐振腔副边软件过流";
CM_ SG_ 2149547880 D2P_ALARM_PriSideOverCurr_HW "谐振腔源边硬件过流";
CM_ SG_ 2149547880 D2P_ALARM_PriSideOverCurr_SW "谐振腔源边软件过流";
CM_ SG_ 2149547880 D2P_ALARM_LowPowerSupplyErr "低压电源供电异常";
CM_ SG_ 2149547880 D2P_ALARM_MBMUComErr "MBMU通讯故障";
CM_ SG_ 2149547880 D2P_ALARM_DCDCMsTeSaplgErr "DCDCMOS管采样温度异常（单点）";
CM_ SG_ 2149547880 D2P_ALARM_DCDCTeSaplgErr "DCDC温度采样异常（双点及以上)";
CM_ SG_ 2149547880 D2P_ALARM_VoltSamplingErr "电压采样异常";
CM_ SG_ 2149547880 D2P_ALARM_HgSdCuSaplgErr "高压侧电流采样异常";
CM_ SG_ 2149547880 D2P_ALARM_CtrlCurrSamplingErr "控制电流采样异常";
CM_ SG_ 2149547880 D2P_ALARM_BypassFail "切旁路失败";
CM_ SG_ 2149547880 D2P_ALARM_Reserve1 "预留数据";
CM_ SG_ 2149547880 D2P_ALARM_Reserve2 "预留数据";
CM_ SG_ 2149547880 D2P_ALARM_Reserve3 "预留数据";
CM_ SG_ 2149547880 D2P_ALARM_Reserve4 "预留数据";
CM_ SG_ 2149547880 D2P_ALARM_Reserve5 "预留数据";
CM_ SG_ 2149547880 D2P_ALARM_Reserve6 "预留数据";
CM_ SG_ 2149547880 D2P_ALARM_Reserve7 "预留数据";
CM_ SG_ 2149547880 D2P_ALARM_Reserve8 "预留数据";
CM_ SG_ 2149547880 D2P_ALARM_Reserve9 "预留数据";
CM_ SG_ 2149547880 D2P_ALARM_Reserve10 "预留数据";
CM_ SG_ 2149547880 D2P_ALARM_Reserve11 "预留数据";
CM_ SG_ 2149547881 D2P_ALARM_EnvExtreOverTemp "环境极限过温";
CM_ SG_ 2149547881 D2P_ALARM_EnvOverTemp "环境过温";
CM_ SG_ 2149547881 D2P_ALARM_MosOverTemp "MOS管过温";
CM_ SG_ 2149547881 D2P_ALARM_MosExtreOverTemp "MOS管极限过温";
CM_ SG_ 2149547881 D2P_ALARM_HighSideOverVolt "高压侧过压故障";
CM_ SG_ 2149547881 D2P_ALARM_HighSideUnderVolt "高压侧欠压故障";
CM_ SG_ 2149547881 D2P_ALARM_LowSideOverVolt "低压侧过压故障";
CM_ SG_ 2149547881 D2P_ALARM_HighSideOverCurr "高压侧过流故障";
CM_ SG_ 2149547881 D2P_ALARM_LowSideOverCurr_HW "低压侧硬件过流故障";
CM_ SG_ 2149547881 D2P_ALARM_LowSideOverCurr_SW "低压侧软件过流故障";
CM_ SG_ 2149547881 D2P_ALARM_SecSideOverCurr_HW "谐振腔副边硬件过流";
CM_ SG_ 2149547881 D2P_ALARM_SecSideOverCurr_SW "谐振腔副边软件过流";
CM_ SG_ 2149547881 D2P_ALARM_PriSideOverCurr_HW "谐振腔源边硬件过流";
CM_ SG_ 2149547881 D2P_ALARM_PriSideOverCurr_SW "谐振腔源边软件过流";
CM_ SG_ 2149547881 D2P_ALARM_LowPowerSupplyErr "低压电源供电异常";
CM_ SG_ 2149547881 D2P_ALARM_MBMUComErr "MBMU通讯故障";
CM_ SG_ 2149547881 D2P_ALARM_DCDCMsTeSaplgErr "DCDCMOS管采样温度异常（单点）";
CM_ SG_ 2149547881 D2P_ALARM_DCDCTeSaplgErr "DCDC温度采样异常（双点及以上)";
CM_ SG_ 2149547881 D2P_ALARM_VoltSamplingErr "电压采样异常";
CM_ SG_ 2149547881 D2P_ALARM_HgSdCuSaplgErr "高压侧电流采样异常";
CM_ SG_ 2149547881 D2P_ALARM_CtrlCurrSamplingErr "控制电流采样异常";
CM_ SG_ 2149547881 D2P_ALARM_BypassFail "切旁路失败";
CM_ SG_ 2149547881 D2P_ALARM_Reserve1 "预留数据";
CM_ SG_ 2149547881 D2P_ALARM_Reserve2 "预留数据";
CM_ SG_ 2149547881 D2P_ALARM_Reserve3 "预留数据";
CM_ SG_ 2149547881 D2P_ALARM_Reserve4 "预留数据";
CM_ SG_ 2149547881 D2P_ALARM_Reserve5 "预留数据";
CM_ SG_ 2149547881 D2P_ALARM_Reserve6 "预留数据";
CM_ SG_ 2149547881 D2P_ALARM_Reserve7 "预留数据";
CM_ SG_ 2149547881 D2P_ALARM_Reserve8 "预留数据";
CM_ SG_ 2149547881 D2P_ALARM_Reserve9 "预留数据";
CM_ SG_ 2149547881 D2P_ALARM_Reserve10 "预留数据";
CM_ SG_ 2149547881 D2P_ALARM_Reserve11 "预留数据";
CM_ SG_ 2149547882 D2P_ALARM_EnvExtreOverTemp "环境极限过温";
CM_ SG_ 2149547882 D2P_ALARM_EnvOverTemp "环境过温";
CM_ SG_ 2149547882 D2P_ALARM_MosOverTemp "MOS管过温";
CM_ SG_ 2149547882 D2P_ALARM_MosExtreOverTemp "MOS管极限过温";
CM_ SG_ 2149547882 D2P_ALARM_HighSideOverVolt "高压侧过压故障";
CM_ SG_ 2149547882 D2P_ALARM_HighSideUnderVolt "高压侧欠压故障";
CM_ SG_ 2149547882 D2P_ALARM_LowSideOverVolt "低压侧过压故障";
CM_ SG_ 2149547882 D2P_ALARM_HighSideOverCurr "高压侧过流故障";
CM_ SG_ 2149547882 D2P_ALARM_LowSideOverCurr_HW "低压侧硬件过流故障";
CM_ SG_ 2149547882 D2P_ALARM_LowSideOverCurr_SW "低压侧软件过流故障";
CM_ SG_ 2149547882 D2P_ALARM_SecSideOverCurr_HW "谐振腔副边硬件过流";
CM_ SG_ 2149547882 D2P_ALARM_SecSideOverCurr_SW "谐振腔副边软件过流";
CM_ SG_ 2149547882 D2P_ALARM_PriSideOverCurr_HW "谐振腔源边硬件过流";
CM_ SG_ 2149547882 D2P_ALARM_PriSideOverCurr_SW "谐振腔源边软件过流";
CM_ SG_ 2149547882 D2P_ALARM_LowPowerSupplyErr "低压电源供电异常";
CM_ SG_ 2149547882 D2P_ALARM_MBMUComErr "MBMU通讯故障";
CM_ SG_ 2149547882 D2P_ALARM_DCDCMsTeSaplgErr "DCDCMOS管采样温度异常（单点）";
CM_ SG_ 2149547882 D2P_ALARM_DCDCTeSaplgErr "DCDC温度采样异常（双点及以上)";
CM_ SG_ 2149547882 D2P_ALARM_VoltSamplingErr "电压采样异常";
CM_ SG_ 2149547882 D2P_ALARM_HgSdCuSaplgErr "高压侧电流采样异常";
CM_ SG_ 2149547882 D2P_ALARM_CtrlCurrSamplingErr "控制电流采样异常";
CM_ SG_ 2149547882 D2P_ALARM_BypassFail "切旁路失败";
CM_ SG_ 2149547882 D2P_ALARM_Reserve1 "预留数据";
CM_ SG_ 2149547882 D2P_ALARM_Reserve2 "预留数据";
CM_ SG_ 2149547882 D2P_ALARM_Reserve3 "预留数据";
CM_ SG_ 2149547882 D2P_ALARM_Reserve4 "预留数据";
CM_ SG_ 2149547882 D2P_ALARM_Reserve5 "预留数据";
CM_ SG_ 2149547882 D2P_ALARM_Reserve6 "预留数据";
CM_ SG_ 2149547882 D2P_ALARM_Reserve7 "预留数据";
CM_ SG_ 2149547882 D2P_ALARM_Reserve8 "预留数据";
CM_ SG_ 2149547882 D2P_ALARM_Reserve9 "预留数据";
CM_ SG_ 2149547882 D2P_ALARM_Reserve10 "预留数据";
CM_ SG_ 2149547882 D2P_ALARM_Reserve11 "预留数据";
CM_ SG_ 2149547883 D2P_ALARM_EnvExtreOverTemp "环境极限过温";
CM_ SG_ 2149547883 D2P_ALARM_EnvOverTemp "环境过温";
CM_ SG_ 2149547883 D2P_ALARM_MosOverTemp "MOS管过温";
CM_ SG_ 2149547883 D2P_ALARM_MosExtreOverTemp "MOS管极限过温";
CM_ SG_ 2149547883 D2P_ALARM_HighSideOverVolt "高压侧过压故障";
CM_ SG_ 2149547883 D2P_ALARM_HighSideUnderVolt "高压侧欠压故障";
CM_ SG_ 2149547883 D2P_ALARM_LowSideOverVolt "低压侧过压故障";
CM_ SG_ 2149547883 D2P_ALARM_HighSideOverCurr "高压侧过流故障";
CM_ SG_ 2149547883 D2P_ALARM_LowSideOverCurr_HW "低压侧硬件过流故障";
CM_ SG_ 2149547883 D2P_ALARM_LowSideOverCurr_SW "低压侧软件过流故障";
CM_ SG_ 2149547883 D2P_ALARM_SecSideOverCurr_HW "谐振腔副边硬件过流";
CM_ SG_ 2149547883 D2P_ALARM_SecSideOverCurr_SW "谐振腔副边软件过流";
CM_ SG_ 2149547883 D2P_ALARM_PriSideOverCurr_HW "谐振腔源边硬件过流";
CM_ SG_ 2149547883 D2P_ALARM_PriSideOverCurr_SW "谐振腔源边软件过流";
CM_ SG_ 2149547883 D2P_ALARM_LowPowerSupplyErr "低压电源供电异常";
CM_ SG_ 2149547883 D2P_ALARM_MBMUComErr "MBMU通讯故障";
CM_ SG_ 2149547883 D2P_ALARM_DCDCMsTeSaplgErr "DCDCMOS管采样温度异常（单点）";
CM_ SG_ 2149547883 D2P_ALARM_DCDCTeSaplgErr "DCDC温度采样异常（双点及以上)";
CM_ SG_ 2149547883 D2P_ALARM_VoltSamplingErr "电压采样异常";
CM_ SG_ 2149547883 D2P_ALARM_HgSdCuSaplgErr "高压侧电流采样异常";
CM_ SG_ 2149547883 D2P_ALARM_CtrlCurrSamplingErr "控制电流采样异常";
CM_ SG_ 2149547883 D2P_ALARM_BypassFail "切旁路失败";
CM_ SG_ 2149547883 D2P_ALARM_Reserve1 "预留数据";
CM_ SG_ 2149547883 D2P_ALARM_Reserve2 "预留数据";
CM_ SG_ 2149547883 D2P_ALARM_Reserve3 "预留数据";
CM_ SG_ 2149547883 D2P_ALARM_Reserve4 "预留数据";
CM_ SG_ 2149547883 D2P_ALARM_Reserve5 "预留数据";
CM_ SG_ 2149547883 D2P_ALARM_Reserve6 "预留数据";
CM_ SG_ 2149547883 D2P_ALARM_Reserve7 "预留数据";
CM_ SG_ 2149547883 D2P_ALARM_Reserve8 "预留数据";
CM_ SG_ 2149547883 D2P_ALARM_Reserve9 "预留数据";
CM_ SG_ 2149547883 D2P_ALARM_Reserve10 "预留数据";
CM_ SG_ 2149547883 D2P_ALARM_Reserve11 "预留数据";
CM_ SG_ 2149547884 D2P_ALARM_EnvExtreOverTemp "环境极限过温";
CM_ SG_ 2149547884 D2P_ALARM_EnvOverTemp "环境过温";
CM_ SG_ 2149547884 D2P_ALARM_MosOverTemp "MOS管过温";
CM_ SG_ 2149547884 D2P_ALARM_MosExtreOverTemp "MOS管极限过温";
CM_ SG_ 2149547884 D2P_ALARM_HighSideOverVolt "高压侧过压故障";
CM_ SG_ 2149547884 D2P_ALARM_HighSideUnderVolt "高压侧欠压故障";
CM_ SG_ 2149547884 D2P_ALARM_LowSideOverVolt "低压侧过压故障";
CM_ SG_ 2149547884 D2P_ALARM_HighSideOverCurr "高压侧过流故障";
CM_ SG_ 2149547884 D2P_ALARM_LowSideOverCurr_HW "低压侧硬件过流故障";
CM_ SG_ 2149547884 D2P_ALARM_LowSideOverCurr_SW "低压侧软件过流故障";
CM_ SG_ 2149547884 D2P_ALARM_SecSideOverCurr_HW "谐振腔副边硬件过流";
CM_ SG_ 2149547884 D2P_ALARM_SecSideOverCurr_SW "谐振腔副边软件过流";
CM_ SG_ 2149547884 D2P_ALARM_PriSideOverCurr_HW "谐振腔源边硬件过流";
CM_ SG_ 2149547884 D2P_ALARM_PriSideOverCurr_SW "谐振腔源边软件过流";
CM_ SG_ 2149547884 D2P_ALARM_LowPowerSupplyErr "低压电源供电异常";
CM_ SG_ 2149547884 D2P_ALARM_MBMUComErr "MBMU通讯故障";
CM_ SG_ 2149547884 D2P_ALARM_DCDCMsTeSaplgErr "DCDCMOS管采样温度异常（单点）";
CM_ SG_ 2149547884 D2P_ALARM_DCDCTeSaplgErr "DCDC温度采样异常（双点及以上)";
CM_ SG_ 2149547884 D2P_ALARM_VoltSamplingErr "电压采样异常";
CM_ SG_ 2149547884 D2P_ALARM_HgSdCuSaplgErr "高压侧电流采样异常";
CM_ SG_ 2149547884 D2P_ALARM_CtrlCurrSamplingErr "控制电流采样异常";
CM_ SG_ 2149547884 D2P_ALARM_BypassFail "切旁路失败";
CM_ SG_ 2149547884 D2P_ALARM_Reserve1 "预留数据";
CM_ SG_ 2149547884 D2P_ALARM_Reserve2 "预留数据";
CM_ SG_ 2149547884 D2P_ALARM_Reserve3 "预留数据";
CM_ SG_ 2149547884 D2P_ALARM_Reserve4 "预留数据";
CM_ SG_ 2149547884 D2P_ALARM_Reserve5 "预留数据";
CM_ SG_ 2149547884 D2P_ALARM_Reserve6 "预留数据";
CM_ SG_ 2149547884 D2P_ALARM_Reserve7 "预留数据";
CM_ SG_ 2149547884 D2P_ALARM_Reserve8 "预留数据";
CM_ SG_ 2149547884 D2P_ALARM_Reserve9 "预留数据";
CM_ SG_ 2149547884 D2P_ALARM_Reserve10 "预留数据";
CM_ SG_ 2149547884 D2P_ALARM_Reserve11 "预留数据";
CM_ SG_ 2149547885 D2P_ALARM_EnvExtreOverTemp "环境极限过温";
CM_ SG_ 2149547885 D2P_ALARM_EnvOverTemp "环境过温";
CM_ SG_ 2149547885 D2P_ALARM_MosOverTemp "MOS管过温";
CM_ SG_ 2149547885 D2P_ALARM_MosExtreOverTemp "MOS管极限过温";
CM_ SG_ 2149547885 D2P_ALARM_HighSideOverVolt "高压侧过压故障";
CM_ SG_ 2149547885 D2P_ALARM_HighSideUnderVolt "高压侧欠压故障";
CM_ SG_ 2149547885 D2P_ALARM_LowSideOverVolt "低压侧过压故障";
CM_ SG_ 2149547885 D2P_ALARM_HighSideOverCurr "高压侧过流故障";
CM_ SG_ 2149547885 D2P_ALARM_LowSideOverCurr_HW "低压侧硬件过流故障";
CM_ SG_ 2149547885 D2P_ALARM_LowSideOverCurr_SW "低压侧软件过流故障";
CM_ SG_ 2149547885 D2P_ALARM_SecSideOverCurr_HW "谐振腔副边硬件过流";
CM_ SG_ 2149547885 D2P_ALARM_SecSideOverCurr_SW "谐振腔副边软件过流";
CM_ SG_ 2149547885 D2P_ALARM_PriSideOverCurr_HW "谐振腔源边硬件过流";
CM_ SG_ 2149547885 D2P_ALARM_PriSideOverCurr_SW "谐振腔源边软件过流";
CM_ SG_ 2149547885 D2P_ALARM_LowPowerSupplyErr "低压电源供电异常";
CM_ SG_ 2149547885 D2P_ALARM_MBMUComErr "MBMU通讯故障";
CM_ SG_ 2149547885 D2P_ALARM_DCDCMsTeSaplgErr "DCDCMOS管采样温度异常（单点）";
CM_ SG_ 2149547885 D2P_ALARM_DCDCTeSaplgErr "DCDC温度采样异常（双点及以上)";
CM_ SG_ 2149547885 D2P_ALARM_VoltSamplingErr "电压采样异常";
CM_ SG_ 2149547885 D2P_ALARM_HgSdCuSaplgErr "高压侧电流采样异常";
CM_ SG_ 2149547885 D2P_ALARM_CtrlCurrSamplingErr "控制电流采样异常";
CM_ SG_ 2149547885 D2P_ALARM_BypassFail "切旁路失败";
CM_ SG_ 2149547885 D2P_ALARM_Reserve1 "预留数据";
CM_ SG_ 2149547885 D2P_ALARM_Reserve2 "预留数据";
CM_ SG_ 2149547885 D2P_ALARM_Reserve3 "预留数据";
CM_ SG_ 2149547885 D2P_ALARM_Reserve4 "预留数据";
CM_ SG_ 2149547885 D2P_ALARM_Reserve5 "预留数据";
CM_ SG_ 2149547885 D2P_ALARM_Reserve6 "预留数据";
CM_ SG_ 2149547885 D2P_ALARM_Reserve7 "预留数据";
CM_ SG_ 2149547885 D2P_ALARM_Reserve8 "预留数据";
CM_ SG_ 2149547885 D2P_ALARM_Reserve9 "预留数据";
CM_ SG_ 2149547885 D2P_ALARM_Reserve10 "预留数据";
CM_ SG_ 2149547885 D2P_ALARM_Reserve11 "预留数据";
CM_ SG_ 2149547886 D2P_ALARM_EnvExtreOverTemp "环境极限过温";
CM_ SG_ 2149547886 D2P_ALARM_EnvOverTemp "环境过温";
CM_ SG_ 2149547886 D2P_ALARM_MosOverTemp "MOS管过温";
CM_ SG_ 2149547886 D2P_ALARM_MosExtreOverTemp "MOS管极限过温";
CM_ SG_ 2149547886 D2P_ALARM_HighSideOverVolt "高压侧过压故障";
CM_ SG_ 2149547886 D2P_ALARM_HighSideUnderVolt "高压侧欠压故障";
CM_ SG_ 2149547886 D2P_ALARM_LowSideOverVolt "低压侧过压故障";
CM_ SG_ 2149547886 D2P_ALARM_HighSideOverCurr "高压侧过流故障";
CM_ SG_ 2149547886 D2P_ALARM_LowSideOverCurr_HW "低压侧硬件过流故障";
CM_ SG_ 2149547886 D2P_ALARM_LowSideOverCurr_SW "低压侧软件过流故障";
CM_ SG_ 2149547886 D2P_ALARM_SecSideOverCurr_HW "谐振腔副边硬件过流";
CM_ SG_ 2149547886 D2P_ALARM_SecSideOverCurr_SW "谐振腔副边软件过流";
CM_ SG_ 2149547886 D2P_ALARM_PriSideOverCurr_HW "谐振腔源边硬件过流";
CM_ SG_ 2149547886 D2P_ALARM_PriSideOverCurr_SW "谐振腔源边软件过流";
CM_ SG_ 2149547886 D2P_ALARM_LowPowerSupplyErr "低压电源供电异常";
CM_ SG_ 2149547886 D2P_ALARM_MBMUComErr "MBMU通讯故障";
CM_ SG_ 2149547886 D2P_ALARM_DCDCMsTeSaplgErr "DCDCMOS管采样温度异常（单点）";
CM_ SG_ 2149547886 D2P_ALARM_DCDCTeSaplgErr "DCDC温度采样异常（双点及以上)";
CM_ SG_ 2149547886 D2P_ALARM_VoltSamplingErr "电压采样异常";
CM_ SG_ 2149547886 D2P_ALARM_HgSdCuSaplgErr "高压侧电流采样异常";
CM_ SG_ 2149547886 D2P_ALARM_CtrlCurrSamplingErr "控制电流采样异常";
CM_ SG_ 2149547886 D2P_ALARM_BypassFail "切旁路失败";
CM_ SG_ 2149547886 D2P_ALARM_Reserve1 "预留数据";
CM_ SG_ 2149547886 D2P_ALARM_Reserve2 "预留数据";
CM_ SG_ 2149547886 D2P_ALARM_Reserve3 "预留数据";
CM_ SG_ 2149547886 D2P_ALARM_Reserve4 "预留数据";
CM_ SG_ 2149547886 D2P_ALARM_Reserve5 "预留数据";
CM_ SG_ 2149547886 D2P_ALARM_Reserve6 "预留数据";
CM_ SG_ 2149547886 D2P_ALARM_Reserve7 "预留数据";
CM_ SG_ 2149547886 D2P_ALARM_Reserve8 "预留数据";
CM_ SG_ 2149547886 D2P_ALARM_Reserve9 "预留数据";
CM_ SG_ 2149547886 D2P_ALARM_Reserve10 "预留数据";
CM_ SG_ 2149547886 D2P_ALARM_Reserve11 "预留数据";
CM_ SG_ 2149547887 D2P_ALARM_EnvExtreOverTemp "环境极限过温";
CM_ SG_ 2149547887 D2P_ALARM_EnvOverTemp "环境过温";
CM_ SG_ 2149547887 D2P_ALARM_MosOverTemp "MOS管过温";
CM_ SG_ 2149547887 D2P_ALARM_MosExtreOverTemp "MOS管极限过温";
CM_ SG_ 2149547887 D2P_ALARM_HighSideOverVolt "高压侧过压故障";
CM_ SG_ 2149547887 D2P_ALARM_HighSideUnderVolt "高压侧欠压故障";
CM_ SG_ 2149547887 D2P_ALARM_LowSideOverVolt "低压侧过压故障";
CM_ SG_ 2149547887 D2P_ALARM_HighSideOverCurr "高压侧过流故障";
CM_ SG_ 2149547887 D2P_ALARM_LowSideOverCurr_HW "低压侧硬件过流故障";
CM_ SG_ 2149547887 D2P_ALARM_LowSideOverCurr_SW "低压侧软件过流故障";
CM_ SG_ 2149547887 D2P_ALARM_SecSideOverCurr_HW "谐振腔副边硬件过流";
CM_ SG_ 2149547887 D2P_ALARM_SecSideOverCurr_SW "谐振腔副边软件过流";
CM_ SG_ 2149547887 D2P_ALARM_PriSideOverCurr_HW "谐振腔源边硬件过流";
CM_ SG_ 2149547887 D2P_ALARM_PriSideOverCurr_SW "谐振腔源边软件过流";
CM_ SG_ 2149547887 D2P_ALARM_LowPowerSupplyErr "低压电源供电异常";
CM_ SG_ 2149547887 D2P_ALARM_MBMUComErr "MBMU通讯故障";
CM_ SG_ 2149547887 D2P_ALARM_DCDCMsTeSaplgErr "DCDCMOS管采样温度异常（单点）";
CM_ SG_ 2149547887 D2P_ALARM_DCDCTeSaplgErr "DCDC温度采样异常（双点及以上)";
CM_ SG_ 2149547887 D2P_ALARM_VoltSamplingErr "电压采样异常";
CM_ SG_ 2149547887 D2P_ALARM_HgSdCuSaplgErr "高压侧电流采样异常";
CM_ SG_ 2149547887 D2P_ALARM_CtrlCurrSamplingErr "控制电流采样异常";
CM_ SG_ 2149547887 D2P_ALARM_BypassFail "切旁路失败";
CM_ SG_ 2149547887 D2P_ALARM_Reserve1 "预留数据";
CM_ SG_ 2149547887 D2P_ALARM_Reserve2 "预留数据";
CM_ SG_ 2149547887 D2P_ALARM_Reserve3 "预留数据";
CM_ SG_ 2149547887 D2P_ALARM_Reserve4 "预留数据";
CM_ SG_ 2149547887 D2P_ALARM_Reserve5 "预留数据";
CM_ SG_ 2149547887 D2P_ALARM_Reserve6 "预留数据";
CM_ SG_ 2149547887 D2P_ALARM_Reserve7 "预留数据";
CM_ SG_ 2149547887 D2P_ALARM_Reserve8 "预留数据";
CM_ SG_ 2149547887 D2P_ALARM_Reserve9 "预留数据";
CM_ SG_ 2149547887 D2P_ALARM_Reserve10 "预留数据";
CM_ SG_ 2149547887 D2P_ALARM_Reserve11 "预留数据";
CM_ SG_ 2149547888 D2P_ALARM_EnvExtreOverTemp "环境极限过温";
CM_ SG_ 2149547888 D2P_ALARM_EnvOverTemp "环境过温";
CM_ SG_ 2149547888 D2P_ALARM_MosOverTemp "MOS管过温";
CM_ SG_ 2149547888 D2P_ALARM_MosExtreOverTemp "MOS管极限过温";
CM_ SG_ 2149547888 D2P_ALARM_HighSideOverVolt "高压侧过压故障";
CM_ SG_ 2149547888 D2P_ALARM_HighSideUnderVolt "高压侧欠压故障";
CM_ SG_ 2149547888 D2P_ALARM_LowSideOverVolt "低压侧过压故障";
CM_ SG_ 2149547888 D2P_ALARM_HighSideOverCurr "高压侧过流故障";
CM_ SG_ 2149547888 D2P_ALARM_LowSideOverCurr_HW "低压侧硬件过流故障";
CM_ SG_ 2149547888 D2P_ALARM_LowSideOverCurr_SW "低压侧软件过流故障";
CM_ SG_ 2149547888 D2P_ALARM_SecSideOverCurr_HW "谐振腔副边硬件过流";
CM_ SG_ 2149547888 D2P_ALARM_SecSideOverCurr_SW "谐振腔副边软件过流";
CM_ SG_ 2149547888 D2P_ALARM_PriSideOverCurr_HW "谐振腔源边硬件过流";
CM_ SG_ 2149547888 D2P_ALARM_PriSideOverCurr_SW "谐振腔源边软件过流";
CM_ SG_ 2149547888 D2P_ALARM_LowPowerSupplyErr "低压电源供电异常";
CM_ SG_ 2149547888 D2P_ALARM_MBMUComErr "MBMU通讯故障";
CM_ SG_ 2149547888 D2P_ALARM_DCDCMsTeSaplgErr "DCDCMOS管采样温度异常（单点）";
CM_ SG_ 2149547888 D2P_ALARM_DCDCTeSaplgErr "DCDC温度采样异常（双点及以上)";
CM_ SG_ 2149547888 D2P_ALARM_VoltSamplingErr "电压采样异常";
CM_ SG_ 2149547888 D2P_ALARM_HgSdCuSaplgErr "高压侧电流采样异常";
CM_ SG_ 2149547888 D2P_ALARM_CtrlCurrSamplingErr "控制电流采样异常";
CM_ SG_ 2149547888 D2P_ALARM_BypassFail "切旁路失败";
CM_ SG_ 2149547888 D2P_ALARM_Reserve1 "预留数据";
CM_ SG_ 2149547888 D2P_ALARM_Reserve2 "预留数据";
CM_ SG_ 2149547888 D2P_ALARM_Reserve3 "预留数据";
CM_ SG_ 2149547888 D2P_ALARM_Reserve4 "预留数据";
CM_ SG_ 2149547888 D2P_ALARM_Reserve5 "预留数据";
CM_ SG_ 2149547888 D2P_ALARM_Reserve6 "预留数据";
CM_ SG_ 2149547888 D2P_ALARM_Reserve7 "预留数据";
CM_ SG_ 2149547888 D2P_ALARM_Reserve8 "预留数据";
CM_ SG_ 2149547888 D2P_ALARM_Reserve9 "预留数据";
CM_ SG_ 2149547888 D2P_ALARM_Reserve10 "预留数据";
CM_ SG_ 2149547888 D2P_ALARM_Reserve11 "预留数据";
CM_ SG_ 2149547889 D2P_ALARM_EnvExtreOverTemp "环境极限过温";
CM_ SG_ 2149547889 D2P_ALARM_EnvOverTemp "环境过温";
CM_ SG_ 2149547889 D2P_ALARM_MosOverTemp "MOS管过温";
CM_ SG_ 2149547889 D2P_ALARM_MosExtreOverTemp "MOS管极限过温";
CM_ SG_ 2149547889 D2P_ALARM_HighSideOverVolt "高压侧过压故障";
CM_ SG_ 2149547889 D2P_ALARM_HighSideUnderVolt "高压侧欠压故障";
CM_ SG_ 2149547889 D2P_ALARM_LowSideOverVolt "低压侧过压故障";
CM_ SG_ 2149547889 D2P_ALARM_HighSideOverCurr "高压侧过流故障";
CM_ SG_ 2149547889 D2P_ALARM_LowSideOverCurr_HW "低压侧硬件过流故障";
CM_ SG_ 2149547889 D2P_ALARM_LowSideOverCurr_SW "低压侧软件过流故障";
CM_ SG_ 2149547889 D2P_ALARM_SecSideOverCurr_HW "谐振腔副边硬件过流";
CM_ SG_ 2149547889 D2P_ALARM_SecSideOverCurr_SW "谐振腔副边软件过流";
CM_ SG_ 2149547889 D2P_ALARM_PriSideOverCurr_HW "谐振腔源边硬件过流";
CM_ SG_ 2149547889 D2P_ALARM_PriSideOverCurr_SW "谐振腔源边软件过流";
CM_ SG_ 2149547889 D2P_ALARM_LowPowerSupplyErr "低压电源供电异常";
CM_ SG_ 2149547889 D2P_ALARM_MBMUComErr "MBMU通讯故障";
CM_ SG_ 2149547889 D2P_ALARM_DCDCMsTeSaplgErr "DCDCMOS管采样温度异常（单点）";
CM_ SG_ 2149547889 D2P_ALARM_DCDCTeSaplgErr "DCDC温度采样异常（双点及以上)";
CM_ SG_ 2149547889 D2P_ALARM_VoltSamplingErr "电压采样异常";
CM_ SG_ 2149547889 D2P_ALARM_HgSdCuSaplgErr "高压侧电流采样异常";
CM_ SG_ 2149547889 D2P_ALARM_CtrlCurrSamplingErr "控制电流采样异常";
CM_ SG_ 2149547889 D2P_ALARM_BypassFail "切旁路失败";
CM_ SG_ 2149547889 D2P_ALARM_Reserve1 "预留数据";
CM_ SG_ 2149547889 D2P_ALARM_Reserve2 "预留数据";
CM_ SG_ 2149547889 D2P_ALARM_Reserve3 "预留数据";
CM_ SG_ 2149547889 D2P_ALARM_Reserve4 "预留数据";
CM_ SG_ 2149547889 D2P_ALARM_Reserve5 "预留数据";
CM_ SG_ 2149547889 D2P_ALARM_Reserve6 "预留数据";
CM_ SG_ 2149547889 D2P_ALARM_Reserve7 "预留数据";
CM_ SG_ 2149547889 D2P_ALARM_Reserve8 "预留数据";
CM_ SG_ 2149547889 D2P_ALARM_Reserve9 "预留数据";
CM_ SG_ 2149547889 D2P_ALARM_Reserve10 "预留数据";
CM_ SG_ 2149547889 D2P_ALARM_Reserve11 "预留数据";
CM_ SG_ 2149547890 D2P_ALARM_EnvExtreOverTemp "环境极限过温";
CM_ SG_ 2149547890 D2P_ALARM_EnvOverTemp "环境过温";
CM_ SG_ 2149547890 D2P_ALARM_MosOverTemp "MOS管过温";
CM_ SG_ 2149547890 D2P_ALARM_MosExtreOverTemp "MOS管极限过温";
CM_ SG_ 2149547890 D2P_ALARM_HighSideOverVolt "高压侧过压故障";
CM_ SG_ 2149547890 D2P_ALARM_HighSideUnderVolt "高压侧欠压故障";
CM_ SG_ 2149547890 D2P_ALARM_LowSideOverVolt "低压侧过压故障";
CM_ SG_ 2149547890 D2P_ALARM_HighSideOverCurr "高压侧过流故障";
CM_ SG_ 2149547890 D2P_ALARM_LowSideOverCurr_HW "低压侧硬件过流故障";
CM_ SG_ 2149547890 D2P_ALARM_LowSideOverCurr_SW "低压侧软件过流故障";
CM_ SG_ 2149547890 D2P_ALARM_SecSideOverCurr_HW "谐振腔副边硬件过流";
CM_ SG_ 2149547890 D2P_ALARM_SecSideOverCurr_SW "谐振腔副边软件过流";
CM_ SG_ 2149547890 D2P_ALARM_PriSideOverCurr_HW "谐振腔源边硬件过流";
CM_ SG_ 2149547890 D2P_ALARM_PriSideOverCurr_SW "谐振腔源边软件过流";
CM_ SG_ 2149547890 D2P_ALARM_LowPowerSupplyErr "低压电源供电异常";
CM_ SG_ 2149547890 D2P_ALARM_MBMUComErr "MBMU通讯故障";
CM_ SG_ 2149547890 D2P_ALARM_DCDCMsTeSaplgErr "DCDCMOS管采样温度异常（单点）";
CM_ SG_ 2149547890 D2P_ALARM_DCDCTeSaplgErr "DCDC温度采样异常（双点及以上)";
CM_ SG_ 2149547890 D2P_ALARM_VoltSamplingErr "电压采样异常";
CM_ SG_ 2149547890 D2P_ALARM_HgSdCuSaplgErr "高压侧电流采样异常";
CM_ SG_ 2149547890 D2P_ALARM_CtrlCurrSamplingErr "控制电流采样异常";
CM_ SG_ 2149547890 D2P_ALARM_BypassFail "切旁路失败";
CM_ SG_ 2149547890 D2P_ALARM_Reserve1 "预留数据";
CM_ SG_ 2149547890 D2P_ALARM_Reserve2 "预留数据";
CM_ SG_ 2149547890 D2P_ALARM_Reserve3 "预留数据";
CM_ SG_ 2149547890 D2P_ALARM_Reserve4 "预留数据";
CM_ SG_ 2149547890 D2P_ALARM_Reserve5 "预留数据";
CM_ SG_ 2149547890 D2P_ALARM_Reserve6 "预留数据";
CM_ SG_ 2149547890 D2P_ALARM_Reserve7 "预留数据";
CM_ SG_ 2149547890 D2P_ALARM_Reserve8 "预留数据";
CM_ SG_ 2149547890 D2P_ALARM_Reserve9 "预留数据";
CM_ SG_ 2149547890 D2P_ALARM_Reserve10 "预留数据";
CM_ SG_ 2149547890 D2P_ALARM_Reserve11 "预留数据";
CM_ SG_ 2149547891 D2P_ALARM_EnvExtreOverTemp "环境极限过温";
CM_ SG_ 2149547891 D2P_ALARM_EnvOverTemp "环境过温";
CM_ SG_ 2149547891 D2P_ALARM_MosOverTemp "MOS管过温";
CM_ SG_ 2149547891 D2P_ALARM_MosExtreOverTemp "MOS管极限过温";
CM_ SG_ 2149547891 D2P_ALARM_HighSideOverVolt "高压侧过压故障";
CM_ SG_ 2149547891 D2P_ALARM_HighSideUnderVolt "高压侧欠压故障";
CM_ SG_ 2149547891 D2P_ALARM_LowSideOverVolt "低压侧过压故障";
CM_ SG_ 2149547891 D2P_ALARM_HighSideOverCurr "高压侧过流故障";
CM_ SG_ 2149547891 D2P_ALARM_LowSideOverCurr_HW "低压侧硬件过流故障";
CM_ SG_ 2149547891 D2P_ALARM_LowSideOverCurr_SW "低压侧软件过流故障";
CM_ SG_ 2149547891 D2P_ALARM_SecSideOverCurr_HW "谐振腔副边硬件过流";
CM_ SG_ 2149547891 D2P_ALARM_SecSideOverCurr_SW "谐振腔副边软件过流";
CM_ SG_ 2149547891 D2P_ALARM_PriSideOverCurr_HW "谐振腔源边硬件过流";
CM_ SG_ 2149547891 D2P_ALARM_PriSideOverCurr_SW "谐振腔源边软件过流";
CM_ SG_ 2149547891 D2P_ALARM_LowPowerSupplyErr "低压电源供电异常";
CM_ SG_ 2149547891 D2P_ALARM_MBMUComErr "MBMU通讯故障";
CM_ SG_ 2149547891 D2P_ALARM_DCDCMsTeSaplgErr "DCDCMOS管采样温度异常（单点）";
CM_ SG_ 2149547891 D2P_ALARM_DCDCTeSaplgErr "DCDC温度采样异常（双点及以上)";
CM_ SG_ 2149547891 D2P_ALARM_VoltSamplingErr "电压采样异常";
CM_ SG_ 2149547891 D2P_ALARM_HgSdCuSaplgErr "高压侧电流采样异常";
CM_ SG_ 2149547891 D2P_ALARM_CtrlCurrSamplingErr "控制电流采样异常";
CM_ SG_ 2149547891 D2P_ALARM_BypassFail "切旁路失败";
CM_ SG_ 2149547891 D2P_ALARM_Reserve1 "预留数据";
CM_ SG_ 2149547891 D2P_ALARM_Reserve2 "预留数据";
CM_ SG_ 2149547891 D2P_ALARM_Reserve3 "预留数据";
CM_ SG_ 2149547891 D2P_ALARM_Reserve4 "预留数据";
CM_ SG_ 2149547891 D2P_ALARM_Reserve5 "预留数据";
CM_ SG_ 2149547891 D2P_ALARM_Reserve6 "预留数据";
CM_ SG_ 2149547891 D2P_ALARM_Reserve7 "预留数据";
CM_ SG_ 2149547891 D2P_ALARM_Reserve8 "预留数据";
CM_ SG_ 2149547891 D2P_ALARM_Reserve9 "预留数据";
CM_ SG_ 2149547891 D2P_ALARM_Reserve10 "预留数据";
CM_ SG_ 2149547891 D2P_ALARM_Reserve11 "预留数据";
CM_ SG_ 2149547892 D2P_ALARM_EnvExtreOverTemp "环境极限过温";
CM_ SG_ 2149547892 D2P_ALARM_EnvOverTemp "环境过温";
CM_ SG_ 2149547892 D2P_ALARM_MosOverTemp "MOS管过温";
CM_ SG_ 2149547892 D2P_ALARM_MosExtreOverTemp "MOS管极限过温";
CM_ SG_ 2149547892 D2P_ALARM_HighSideOverVolt "高压侧过压故障";
CM_ SG_ 2149547892 D2P_ALARM_HighSideUnderVolt "高压侧欠压故障";
CM_ SG_ 2149547892 D2P_ALARM_LowSideOverVolt "低压侧过压故障";
CM_ SG_ 2149547892 D2P_ALARM_HighSideOverCurr "高压侧过流故障";
CM_ SG_ 2149547892 D2P_ALARM_LowSideOverCurr_HW "低压侧硬件过流故障";
CM_ SG_ 2149547892 D2P_ALARM_LowSideOverCurr_SW "低压侧软件过流故障";
CM_ SG_ 2149547892 D2P_ALARM_SecSideOverCurr_HW "谐振腔副边硬件过流";
CM_ SG_ 2149547892 D2P_ALARM_SecSideOverCurr_SW "谐振腔副边软件过流";
CM_ SG_ 2149547892 D2P_ALARM_PriSideOverCurr_HW "谐振腔源边硬件过流";
CM_ SG_ 2149547892 D2P_ALARM_PriSideOverCurr_SW "谐振腔源边软件过流";
CM_ SG_ 2149547892 D2P_ALARM_LowPowerSupplyErr "低压电源供电异常";
CM_ SG_ 2149547892 D2P_ALARM_MBMUComErr "MBMU通讯故障";
CM_ SG_ 2149547892 D2P_ALARM_DCDCMsTeSaplgErr "DCDCMOS管采样温度异常（单点）";
CM_ SG_ 2149547892 D2P_ALARM_DCDCTeSaplgErr "DCDC温度采样异常（双点及以上)";
CM_ SG_ 2149547892 D2P_ALARM_VoltSamplingErr "电压采样异常";
CM_ SG_ 2149547892 D2P_ALARM_HgSdCuSaplgErr "高压侧电流采样异常";
CM_ SG_ 2149547892 D2P_ALARM_CtrlCurrSamplingErr "控制电流采样异常";
CM_ SG_ 2149547892 D2P_ALARM_BypassFail "切旁路失败";
CM_ SG_ 2149547892 D2P_ALARM_Reserve1 "预留数据";
CM_ SG_ 2149547892 D2P_ALARM_Reserve2 "预留数据";
CM_ SG_ 2149547892 D2P_ALARM_Reserve3 "预留数据";
CM_ SG_ 2149547892 D2P_ALARM_Reserve4 "预留数据";
CM_ SG_ 2149547892 D2P_ALARM_Reserve5 "预留数据";
CM_ SG_ 2149547892 D2P_ALARM_Reserve6 "预留数据";
CM_ SG_ 2149547892 D2P_ALARM_Reserve7 "预留数据";
CM_ SG_ 2149547892 D2P_ALARM_Reserve8 "预留数据";
CM_ SG_ 2149547892 D2P_ALARM_Reserve9 "预留数据";
CM_ SG_ 2149547892 D2P_ALARM_Reserve10 "预留数据";
CM_ SG_ 2149547892 D2P_ALARM_Reserve11 "预留数据";
CM_ SG_ 2149547893 D2P_ALARM_EnvExtreOverTemp "环境极限过温";
CM_ SG_ 2149547893 D2P_ALARM_EnvOverTemp "环境过温";
CM_ SG_ 2149547893 D2P_ALARM_MosOverTemp "MOS管过温";
CM_ SG_ 2149547893 D2P_ALARM_MosExtreOverTemp "MOS管极限过温";
CM_ SG_ 2149547893 D2P_ALARM_HighSideOverVolt "高压侧过压故障";
CM_ SG_ 2149547893 D2P_ALARM_HighSideUnderVolt "高压侧欠压故障";
CM_ SG_ 2149547893 D2P_ALARM_LowSideOverVolt "低压侧过压故障";
CM_ SG_ 2149547893 D2P_ALARM_HighSideOverCurr "高压侧过流故障";
CM_ SG_ 2149547893 D2P_ALARM_LowSideOverCurr_HW "低压侧硬件过流故障";
CM_ SG_ 2149547893 D2P_ALARM_LowSideOverCurr_SW "低压侧软件过流故障";
CM_ SG_ 2149547893 D2P_ALARM_SecSideOverCurr_HW "谐振腔副边硬件过流";
CM_ SG_ 2149547893 D2P_ALARM_SecSideOverCurr_SW "谐振腔副边软件过流";
CM_ SG_ 2149547893 D2P_ALARM_PriSideOverCurr_HW "谐振腔源边硬件过流";
CM_ SG_ 2149547893 D2P_ALARM_PriSideOverCurr_SW "谐振腔源边软件过流";
CM_ SG_ 2149547893 D2P_ALARM_LowPowerSupplyErr "低压电源供电异常";
CM_ SG_ 2149547893 D2P_ALARM_MBMUComErr "MBMU通讯故障";
CM_ SG_ 2149547893 D2P_ALARM_DCDCMsTeSaplgErr "DCDCMOS管采样温度异常（单点）";
CM_ SG_ 2149547893 D2P_ALARM_DCDCTeSaplgErr "DCDC温度采样异常（双点及以上)";
CM_ SG_ 2149547893 D2P_ALARM_VoltSamplingErr "电压采样异常";
CM_ SG_ 2149547893 D2P_ALARM_HgSdCuSaplgErr "高压侧电流采样异常";
CM_ SG_ 2149547893 D2P_ALARM_CtrlCurrSamplingErr "控制电流采样异常";
CM_ SG_ 2149547893 D2P_ALARM_BypassFail "切旁路失败";
CM_ SG_ 2149547893 D2P_ALARM_Reserve1 "预留数据";
CM_ SG_ 2149547893 D2P_ALARM_Reserve2 "预留数据";
CM_ SG_ 2149547893 D2P_ALARM_Reserve3 "预留数据";
CM_ SG_ 2149547893 D2P_ALARM_Reserve4 "预留数据";
CM_ SG_ 2149547893 D2P_ALARM_Reserve5 "预留数据";
CM_ SG_ 2149547893 D2P_ALARM_Reserve6 "预留数据";
CM_ SG_ 2149547893 D2P_ALARM_Reserve7 "预留数据";
CM_ SG_ 2149547893 D2P_ALARM_Reserve8 "预留数据";
CM_ SG_ 2149547893 D2P_ALARM_Reserve9 "预留数据";
CM_ SG_ 2149547893 D2P_ALARM_Reserve10 "预留数据";
CM_ SG_ 2149547893 D2P_ALARM_Reserve11 "预留数据";
CM_ SG_ 2149547894 D2P_ALARM_EnvExtreOverTemp "环境极限过温";
CM_ SG_ 2149547894 D2P_ALARM_EnvOverTemp "环境过温";
CM_ SG_ 2149547894 D2P_ALARM_MosOverTemp "MOS管过温";
CM_ SG_ 2149547894 D2P_ALARM_MosExtreOverTemp "MOS管极限过温";
CM_ SG_ 2149547894 D2P_ALARM_HighSideOverVolt "高压侧过压故障";
CM_ SG_ 2149547894 D2P_ALARM_HighSideUnderVolt "高压侧欠压故障";
CM_ SG_ 2149547894 D2P_ALARM_LowSideOverVolt "低压侧过压故障";
CM_ SG_ 2149547894 D2P_ALARM_HighSideOverCurr "高压侧过流故障";
CM_ SG_ 2149547894 D2P_ALARM_LowSideOverCurr_HW "低压侧硬件过流故障";
CM_ SG_ 2149547894 D2P_ALARM_LowSideOverCurr_SW "低压侧软件过流故障";
CM_ SG_ 2149547894 D2P_ALARM_SecSideOverCurr_HW "谐振腔副边硬件过流";
CM_ SG_ 2149547894 D2P_ALARM_SecSideOverCurr_SW "谐振腔副边软件过流";
CM_ SG_ 2149547894 D2P_ALARM_PriSideOverCurr_HW "谐振腔源边硬件过流";
CM_ SG_ 2149547894 D2P_ALARM_PriSideOverCurr_SW "谐振腔源边软件过流";
CM_ SG_ 2149547894 D2P_ALARM_LowPowerSupplyErr "低压电源供电异常";
CM_ SG_ 2149547894 D2P_ALARM_MBMUComErr "MBMU通讯故障";
CM_ SG_ 2149547894 D2P_ALARM_DCDCMsTeSaplgErr "DCDCMOS管采样温度异常（单点）";
CM_ SG_ 2149547894 D2P_ALARM_DCDCTeSaplgErr "DCDC温度采样异常（双点及以上)";
CM_ SG_ 2149547894 D2P_ALARM_VoltSamplingErr "电压采样异常";
CM_ SG_ 2149547894 D2P_ALARM_HgSdCuSaplgErr "高压侧电流采样异常";
CM_ SG_ 2149547894 D2P_ALARM_CtrlCurrSamplingErr "控制电流采样异常";
CM_ SG_ 2149547894 D2P_ALARM_BypassFail "切旁路失败";
CM_ SG_ 2149547894 D2P_ALARM_Reserve1 "预留数据";
CM_ SG_ 2149547894 D2P_ALARM_Reserve2 "预留数据";
CM_ SG_ 2149547894 D2P_ALARM_Reserve3 "预留数据";
CM_ SG_ 2149547894 D2P_ALARM_Reserve4 "预留数据";
CM_ SG_ 2149547894 D2P_ALARM_Reserve5 "预留数据";
CM_ SG_ 2149547894 D2P_ALARM_Reserve6 "预留数据";
CM_ SG_ 2149547894 D2P_ALARM_Reserve7 "预留数据";
CM_ SG_ 2149547894 D2P_ALARM_Reserve8 "预留数据";
CM_ SG_ 2149547894 D2P_ALARM_Reserve9 "预留数据";
CM_ SG_ 2149547894 D2P_ALARM_Reserve10 "预留数据";
CM_ SG_ 2149547894 D2P_ALARM_Reserve11 "预留数据";
CM_ SG_ 2149547895 D2P_ALARM_EnvExtreOverTemp "环境极限过温";
CM_ SG_ 2149547895 D2P_ALARM_EnvOverTemp "环境过温";
CM_ SG_ 2149547895 D2P_ALARM_MosOverTemp "MOS管过温";
CM_ SG_ 2149547895 D2P_ALARM_MosExtreOverTemp "MOS管极限过温";
CM_ SG_ 2149547895 D2P_ALARM_HighSideOverVolt "高压侧过压故障";
CM_ SG_ 2149547895 D2P_ALARM_HighSideUnderVolt "高压侧欠压故障";
CM_ SG_ 2149547895 D2P_ALARM_LowSideOverVolt "低压侧过压故障";
CM_ SG_ 2149547895 D2P_ALARM_HighSideOverCurr "高压侧过流故障";
CM_ SG_ 2149547895 D2P_ALARM_LowSideOverCurr_HW "低压侧硬件过流故障";
CM_ SG_ 2149547895 D2P_ALARM_LowSideOverCurr_SW "低压侧软件过流故障";
CM_ SG_ 2149547895 D2P_ALARM_SecSideOverCurr_HW "谐振腔副边硬件过流";
CM_ SG_ 2149547895 D2P_ALARM_SecSideOverCurr_SW "谐振腔副边软件过流";
CM_ SG_ 2149547895 D2P_ALARM_PriSideOverCurr_HW "谐振腔源边硬件过流";
CM_ SG_ 2149547895 D2P_ALARM_PriSideOverCurr_SW "谐振腔源边软件过流";
CM_ SG_ 2149547895 D2P_ALARM_LowPowerSupplyErr "低压电源供电异常";
CM_ SG_ 2149547895 D2P_ALARM_MBMUComErr "MBMU通讯故障";
CM_ SG_ 2149547895 D2P_ALARM_DCDCMsTeSaplgErr "DCDCMOS管采样温度异常（单点）";
CM_ SG_ 2149547895 D2P_ALARM_DCDCTeSaplgErr "DCDC温度采样异常（双点及以上)";
CM_ SG_ 2149547895 D2P_ALARM_VoltSamplingErr "电压采样异常";
CM_ SG_ 2149547895 D2P_ALARM_HgSdCuSaplgErr "高压侧电流采样异常";
CM_ SG_ 2149547895 D2P_ALARM_CtrlCurrSamplingErr "控制电流采样异常";
CM_ SG_ 2149547895 D2P_ALARM_BypassFail "切旁路失败";
CM_ SG_ 2149547895 D2P_ALARM_Reserve1 "预留数据";
CM_ SG_ 2149547895 D2P_ALARM_Reserve2 "预留数据";
CM_ SG_ 2149547895 D2P_ALARM_Reserve3 "预留数据";
CM_ SG_ 2149547895 D2P_ALARM_Reserve4 "预留数据";
CM_ SG_ 2149547895 D2P_ALARM_Reserve5 "预留数据";
CM_ SG_ 2149547895 D2P_ALARM_Reserve6 "预留数据";
CM_ SG_ 2149547895 D2P_ALARM_Reserve7 "预留数据";
CM_ SG_ 2149547895 D2P_ALARM_Reserve8 "预留数据";
CM_ SG_ 2149547895 D2P_ALARM_Reserve9 "预留数据";
CM_ SG_ 2149547895 D2P_ALARM_Reserve10 "预留数据";
CM_ SG_ 2149547895 D2P_ALARM_Reserve11 "预留数据";
CM_ SG_ 2149547896 D2P_ALARM_EnvExtreOverTemp "环境极限过温";
CM_ SG_ 2149547896 D2P_ALARM_EnvOverTemp "环境过温";
CM_ SG_ 2149547896 D2P_ALARM_MosOverTemp "MOS管过温";
CM_ SG_ 2149547896 D2P_ALARM_MosExtreOverTemp "MOS管极限过温";
CM_ SG_ 2149547896 D2P_ALARM_HighSideOverVolt "高压侧过压故障";
CM_ SG_ 2149547896 D2P_ALARM_HighSideUnderVolt "高压侧欠压故障";
CM_ SG_ 2149547896 D2P_ALARM_LowSideOverVolt "低压侧过压故障";
CM_ SG_ 2149547896 D2P_ALARM_HighSideOverCurr "高压侧过流故障";
CM_ SG_ 2149547896 D2P_ALARM_LowSideOverCurr_HW "低压侧硬件过流故障";
CM_ SG_ 2149547896 D2P_ALARM_LowSideOverCurr_SW "低压侧软件过流故障";
CM_ SG_ 2149547896 D2P_ALARM_SecSideOverCurr_HW "谐振腔副边硬件过流";
CM_ SG_ 2149547896 D2P_ALARM_SecSideOverCurr_SW "谐振腔副边软件过流";
CM_ SG_ 2149547896 D2P_ALARM_PriSideOverCurr_HW "谐振腔源边硬件过流";
CM_ SG_ 2149547896 D2P_ALARM_PriSideOverCurr_SW "谐振腔源边软件过流";
CM_ SG_ 2149547896 D2P_ALARM_LowPowerSupplyErr "低压电源供电异常";
CM_ SG_ 2149547896 D2P_ALARM_MBMUComErr "MBMU通讯故障";
CM_ SG_ 2149547896 D2P_ALARM_DCDCMsTeSaplgErr "DCDCMOS管采样温度异常（单点）";
CM_ SG_ 2149547896 D2P_ALARM_DCDCTeSaplgErr "DCDC温度采样异常（双点及以上)";
CM_ SG_ 2149547896 D2P_ALARM_VoltSamplingErr "电压采样异常";
CM_ SG_ 2149547896 D2P_ALARM_HgSdCuSaplgErr "高压侧电流采样异常";
CM_ SG_ 2149547896 D2P_ALARM_CtrlCurrSamplingErr "控制电流采样异常";
CM_ SG_ 2149547896 D2P_ALARM_BypassFail "切旁路失败";
CM_ SG_ 2149547896 D2P_ALARM_Reserve1 "预留数据";
CM_ SG_ 2149547896 D2P_ALARM_Reserve2 "预留数据";
CM_ SG_ 2149547896 D2P_ALARM_Reserve3 "预留数据";
CM_ SG_ 2149547896 D2P_ALARM_Reserve4 "预留数据";
CM_ SG_ 2149547896 D2P_ALARM_Reserve5 "预留数据";
CM_ SG_ 2149547896 D2P_ALARM_Reserve6 "预留数据";
CM_ SG_ 2149547896 D2P_ALARM_Reserve7 "预留数据";
CM_ SG_ 2149547896 D2P_ALARM_Reserve8 "预留数据";
CM_ SG_ 2149547896 D2P_ALARM_Reserve9 "预留数据";
CM_ SG_ 2149547896 D2P_ALARM_Reserve10 "预留数据";
CM_ SG_ 2149547896 D2P_ALARM_Reserve11 "预留数据";
CM_ SG_ 2149547897 D2P_ALARM_EnvExtreOverTemp "环境极限过温";
CM_ SG_ 2149547897 D2P_ALARM_EnvOverTemp "环境过温";
CM_ SG_ 2149547897 D2P_ALARM_MosOverTemp "MOS管过温";
CM_ SG_ 2149547897 D2P_ALARM_MosExtreOverTemp "MOS管极限过温";
CM_ SG_ 2149547897 D2P_ALARM_HighSideOverVolt "高压侧过压故障";
CM_ SG_ 2149547897 D2P_ALARM_HighSideUnderVolt "高压侧欠压故障";
CM_ SG_ 2149547897 D2P_ALARM_LowSideOverVolt "低压侧过压故障";
CM_ SG_ 2149547897 D2P_ALARM_HighSideOverCurr "高压侧过流故障";
CM_ SG_ 2149547897 D2P_ALARM_LowSideOverCurr_HW "低压侧硬件过流故障";
CM_ SG_ 2149547897 D2P_ALARM_LowSideOverCurr_SW "低压侧软件过流故障";
CM_ SG_ 2149547897 D2P_ALARM_SecSideOverCurr_HW "谐振腔副边硬件过流";
CM_ SG_ 2149547897 D2P_ALARM_SecSideOverCurr_SW "谐振腔副边软件过流";
CM_ SG_ 2149547897 D2P_ALARM_PriSideOverCurr_HW "谐振腔源边硬件过流";
CM_ SG_ 2149547897 D2P_ALARM_PriSideOverCurr_SW "谐振腔源边软件过流";
CM_ SG_ 2149547897 D2P_ALARM_LowPowerSupplyErr "低压电源供电异常";
CM_ SG_ 2149547897 D2P_ALARM_MBMUComErr "MBMU通讯故障";
CM_ SG_ 2149547897 D2P_ALARM_DCDCMsTeSaplgErr "DCDCMOS管采样温度异常（单点）";
CM_ SG_ 2149547897 D2P_ALARM_DCDCTeSaplgErr "DCDC温度采样异常（双点及以上)";
CM_ SG_ 2149547897 D2P_ALARM_VoltSamplingErr "电压采样异常";
CM_ SG_ 2149547897 D2P_ALARM_HgSdCuSaplgErr "高压侧电流采样异常";
CM_ SG_ 2149547897 D2P_ALARM_CtrlCurrSamplingErr "控制电流采样异常";
CM_ SG_ 2149547897 D2P_ALARM_BypassFail "切旁路失败";
CM_ SG_ 2149547897 D2P_ALARM_Reserve1 "预留数据";
CM_ SG_ 2149547897 D2P_ALARM_Reserve2 "预留数据";
CM_ SG_ 2149547897 D2P_ALARM_Reserve3 "预留数据";
CM_ SG_ 2149547897 D2P_ALARM_Reserve4 "预留数据";
CM_ SG_ 2149547897 D2P_ALARM_Reserve5 "预留数据";
CM_ SG_ 2149547897 D2P_ALARM_Reserve6 "预留数据";
CM_ SG_ 2149547897 D2P_ALARM_Reserve7 "预留数据";
CM_ SG_ 2149547897 D2P_ALARM_Reserve8 "预留数据";
CM_ SG_ 2149547897 D2P_ALARM_Reserve9 "预留数据";
CM_ SG_ 2149547897 D2P_ALARM_Reserve10 "预留数据";
CM_ SG_ 2149547897 D2P_ALARM_Reserve11 "预留数据";
CM_ SG_ 2149547898 D2P_ALARM_EnvExtreOverTemp "环境极限过温";
CM_ SG_ 2149547898 D2P_ALARM_EnvOverTemp "环境过温";
CM_ SG_ 2149547898 D2P_ALARM_MosOverTemp "MOS管过温";
CM_ SG_ 2149547898 D2P_ALARM_MosExtreOverTemp "MOS管极限过温";
CM_ SG_ 2149547898 D2P_ALARM_HighSideOverVolt "高压侧过压故障";
CM_ SG_ 2149547898 D2P_ALARM_HighSideUnderVolt "高压侧欠压故障";
CM_ SG_ 2149547898 D2P_ALARM_LowSideOverVolt "低压侧过压故障";
CM_ SG_ 2149547898 D2P_ALARM_HighSideOverCurr "高压侧过流故障";
CM_ SG_ 2149547898 D2P_ALARM_LowSideOverCurr_HW "低压侧硬件过流故障";
CM_ SG_ 2149547898 D2P_ALARM_LowSideOverCurr_SW "低压侧软件过流故障";
CM_ SG_ 2149547898 D2P_ALARM_SecSideOverCurr_HW "谐振腔副边硬件过流";
CM_ SG_ 2149547898 D2P_ALARM_SecSideOverCurr_SW "谐振腔副边软件过流";
CM_ SG_ 2149547898 D2P_ALARM_PriSideOverCurr_HW "谐振腔源边硬件过流";
CM_ SG_ 2149547898 D2P_ALARM_PriSideOverCurr_SW "谐振腔源边软件过流";
CM_ SG_ 2149547898 D2P_ALARM_LowPowerSupplyErr "低压电源供电异常";
CM_ SG_ 2149547898 D2P_ALARM_MBMUComErr "MBMU通讯故障";
CM_ SG_ 2149547898 D2P_ALARM_DCDCMsTeSaplgErr "DCDCMOS管采样温度异常（单点）";
CM_ SG_ 2149547898 D2P_ALARM_DCDCTeSaplgErr "DCDC温度采样异常（双点及以上)";
CM_ SG_ 2149547898 D2P_ALARM_VoltSamplingErr "电压采样异常";
CM_ SG_ 2149547898 D2P_ALARM_HgSdCuSaplgErr "高压侧电流采样异常";
CM_ SG_ 2149547898 D2P_ALARM_CtrlCurrSamplingErr "控制电流采样异常";
CM_ SG_ 2149547898 D2P_ALARM_BypassFail "切旁路失败";
CM_ SG_ 2149547898 D2P_ALARM_Reserve1 "预留数据";
CM_ SG_ 2149547898 D2P_ALARM_Reserve2 "预留数据";
CM_ SG_ 2149547898 D2P_ALARM_Reserve3 "预留数据";
CM_ SG_ 2149547898 D2P_ALARM_Reserve4 "预留数据";
CM_ SG_ 2149547898 D2P_ALARM_Reserve5 "预留数据";
CM_ SG_ 2149547898 D2P_ALARM_Reserve6 "预留数据";
CM_ SG_ 2149547898 D2P_ALARM_Reserve7 "预留数据";
CM_ SG_ 2149547898 D2P_ALARM_Reserve8 "预留数据";
CM_ SG_ 2149547898 D2P_ALARM_Reserve9 "预留数据";
CM_ SG_ 2149547898 D2P_ALARM_Reserve10 "预留数据";
CM_ SG_ 2149547898 D2P_ALARM_Reserve11 "预留数据";
CM_ SG_ 2149547899 D2P_ALARM_EnvExtreOverTemp "环境极限过温";
CM_ SG_ 2149547899 D2P_ALARM_EnvOverTemp "环境过温";
CM_ SG_ 2149547899 D2P_ALARM_MosOverTemp "MOS管过温";
CM_ SG_ 2149547899 D2P_ALARM_MosExtreOverTemp "MOS管极限过温";
CM_ SG_ 2149547899 D2P_ALARM_HighSideOverVolt "高压侧过压故障";
CM_ SG_ 2149547899 D2P_ALARM_HighSideUnderVolt "高压侧欠压故障";
CM_ SG_ 2149547899 D2P_ALARM_LowSideOverVolt "低压侧过压故障";
CM_ SG_ 2149547899 D2P_ALARM_HighSideOverCurr "高压侧过流故障";
CM_ SG_ 2149547899 D2P_ALARM_LowSideOverCurr_HW "低压侧硬件过流故障";
CM_ SG_ 2149547899 D2P_ALARM_LowSideOverCurr_SW "低压侧软件过流故障";
CM_ SG_ 2149547899 D2P_ALARM_SecSideOverCurr_HW "谐振腔副边硬件过流";
CM_ SG_ 2149547899 D2P_ALARM_SecSideOverCurr_SW "谐振腔副边软件过流";
CM_ SG_ 2149547899 D2P_ALARM_PriSideOverCurr_HW "谐振腔源边硬件过流";
CM_ SG_ 2149547899 D2P_ALARM_PriSideOverCurr_SW "谐振腔源边软件过流";
CM_ SG_ 2149547899 D2P_ALARM_LowPowerSupplyErr "低压电源供电异常";
CM_ SG_ 2149547899 D2P_ALARM_MBMUComErr "MBMU通讯故障";
CM_ SG_ 2149547899 D2P_ALARM_DCDCMsTeSaplgErr "DCDCMOS管采样温度异常（单点）";
CM_ SG_ 2149547899 D2P_ALARM_DCDCTeSaplgErr "DCDC温度采样异常（双点及以上)";
CM_ SG_ 2149547899 D2P_ALARM_VoltSamplingErr "电压采样异常";
CM_ SG_ 2149547899 D2P_ALARM_HgSdCuSaplgErr "高压侧电流采样异常";
CM_ SG_ 2149547899 D2P_ALARM_CtrlCurrSamplingErr "控制电流采样异常";
CM_ SG_ 2149547899 D2P_ALARM_BypassFail "切旁路失败";
CM_ SG_ 2149547899 D2P_ALARM_Reserve1 "预留数据";
CM_ SG_ 2149547899 D2P_ALARM_Reserve2 "预留数据";
CM_ SG_ 2149547899 D2P_ALARM_Reserve3 "预留数据";
CM_ SG_ 2149547899 D2P_ALARM_Reserve4 "预留数据";
CM_ SG_ 2149547899 D2P_ALARM_Reserve5 "预留数据";
CM_ SG_ 2149547899 D2P_ALARM_Reserve6 "预留数据";
CM_ SG_ 2149547899 D2P_ALARM_Reserve7 "预留数据";
CM_ SG_ 2149547899 D2P_ALARM_Reserve8 "预留数据";
CM_ SG_ 2149547899 D2P_ALARM_Reserve9 "预留数据";
CM_ SG_ 2149547899 D2P_ALARM_Reserve10 "预留数据";
CM_ SG_ 2149547899 D2P_ALARM_Reserve11 "预留数据";
CM_ SG_ 2149547900 D2P_ALARM_EnvExtreOverTemp "环境极限过温";
CM_ SG_ 2149547900 D2P_ALARM_EnvOverTemp "环境过温";
CM_ SG_ 2149547900 D2P_ALARM_MosOverTemp "MOS管过温";
CM_ SG_ 2149547900 D2P_ALARM_MosExtreOverTemp "MOS管极限过温";
CM_ SG_ 2149547900 D2P_ALARM_HighSideOverVolt "高压侧过压故障";
CM_ SG_ 2149547900 D2P_ALARM_HighSideUnderVolt "高压侧欠压故障";
CM_ SG_ 2149547900 D2P_ALARM_LowSideOverVolt "低压侧过压故障";
CM_ SG_ 2149547900 D2P_ALARM_HighSideOverCurr "高压侧过流故障";
CM_ SG_ 2149547900 D2P_ALARM_LowSideOverCurr_HW "低压侧硬件过流故障";
CM_ SG_ 2149547900 D2P_ALARM_LowSideOverCurr_SW "低压侧软件过流故障";
CM_ SG_ 2149547900 D2P_ALARM_SecSideOverCurr_HW "谐振腔副边硬件过流";
CM_ SG_ 2149547900 D2P_ALARM_SecSideOverCurr_SW "谐振腔副边软件过流";
CM_ SG_ 2149547900 D2P_ALARM_PriSideOverCurr_HW "谐振腔源边硬件过流";
CM_ SG_ 2149547900 D2P_ALARM_PriSideOverCurr_SW "谐振腔源边软件过流";
CM_ SG_ 2149547900 D2P_ALARM_LowPowerSupplyErr "低压电源供电异常";
CM_ SG_ 2149547900 D2P_ALARM_MBMUComErr "MBMU通讯故障";
CM_ SG_ 2149547900 D2P_ALARM_DCDCMsTeSaplgErr "DCDCMOS管采样温度异常（单点）";
CM_ SG_ 2149547900 D2P_ALARM_DCDCTeSaplgErr "DCDC温度采样异常（双点及以上)";
CM_ SG_ 2149547900 D2P_ALARM_VoltSamplingErr "电压采样异常";
CM_ SG_ 2149547900 D2P_ALARM_HgSdCuSaplgErr "高压侧电流采样异常";
CM_ SG_ 2149547900 D2P_ALARM_CtrlCurrSamplingErr "控制电流采样异常";
CM_ SG_ 2149547900 D2P_ALARM_BypassFail "切旁路失败";
CM_ SG_ 2149547900 D2P_ALARM_Reserve1 "预留数据";
CM_ SG_ 2149547900 D2P_ALARM_Reserve2 "预留数据";
CM_ SG_ 2149547900 D2P_ALARM_Reserve3 "预留数据";
CM_ SG_ 2149547900 D2P_ALARM_Reserve4 "预留数据";
CM_ SG_ 2149547900 D2P_ALARM_Reserve5 "预留数据";
CM_ SG_ 2149547900 D2P_ALARM_Reserve6 "预留数据";
CM_ SG_ 2149547900 D2P_ALARM_Reserve7 "预留数据";
CM_ SG_ 2149547900 D2P_ALARM_Reserve8 "预留数据";
CM_ SG_ 2149547900 D2P_ALARM_Reserve9 "预留数据";
CM_ SG_ 2149547900 D2P_ALARM_Reserve10 "预留数据";
CM_ SG_ 2149547900 D2P_ALARM_Reserve11 "预留数据";
CM_ SG_ 2149547901 D2P_ALARM_EnvExtreOverTemp "环境极限过温";
CM_ SG_ 2149547901 D2P_ALARM_EnvOverTemp "环境过温";
CM_ SG_ 2149547901 D2P_ALARM_MosOverTemp "MOS管过温";
CM_ SG_ 2149547901 D2P_ALARM_MosExtreOverTemp "MOS管极限过温";
CM_ SG_ 2149547901 D2P_ALARM_HighSideOverVolt "高压侧过压故障";
CM_ SG_ 2149547901 D2P_ALARM_HighSideUnderVolt "高压侧欠压故障";
CM_ SG_ 2149547901 D2P_ALARM_LowSideOverVolt "低压侧过压故障";
CM_ SG_ 2149547901 D2P_ALARM_HighSideOverCurr "高压侧过流故障";
CM_ SG_ 2149547901 D2P_ALARM_LowSideOverCurr_HW "低压侧硬件过流故障";
CM_ SG_ 2149547901 D2P_ALARM_LowSideOverCurr_SW "低压侧软件过流故障";
CM_ SG_ 2149547901 D2P_ALARM_SecSideOverCurr_HW "谐振腔副边硬件过流";
CM_ SG_ 2149547901 D2P_ALARM_SecSideOverCurr_SW "谐振腔副边软件过流";
CM_ SG_ 2149547901 D2P_ALARM_PriSideOverCurr_HW "谐振腔源边硬件过流";
CM_ SG_ 2149547901 D2P_ALARM_PriSideOverCurr_SW "谐振腔源边软件过流";
CM_ SG_ 2149547901 D2P_ALARM_LowPowerSupplyErr "低压电源供电异常";
CM_ SG_ 2149547901 D2P_ALARM_MBMUComErr "MBMU通讯故障";
CM_ SG_ 2149547901 D2P_ALARM_DCDCMsTeSaplgErr "DCDCMOS管采样温度异常（单点）";
CM_ SG_ 2149547901 D2P_ALARM_DCDCTeSaplgErr "DCDC温度采样异常（双点及以上)";
CM_ SG_ 2149547901 D2P_ALARM_VoltSamplingErr "电压采样异常";
CM_ SG_ 2149547901 D2P_ALARM_HgSdCuSaplgErr "高压侧电流采样异常";
CM_ SG_ 2149547901 D2P_ALARM_CtrlCurrSamplingErr "控制电流采样异常";
CM_ SG_ 2149547901 D2P_ALARM_BypassFail "切旁路失败";
CM_ SG_ 2149547901 D2P_ALARM_Reserve1 "预留数据";
CM_ SG_ 2149547901 D2P_ALARM_Reserve2 "预留数据";
CM_ SG_ 2149547901 D2P_ALARM_Reserve3 "预留数据";
CM_ SG_ 2149547901 D2P_ALARM_Reserve4 "预留数据";
CM_ SG_ 2149547901 D2P_ALARM_Reserve5 "预留数据";
CM_ SG_ 2149547901 D2P_ALARM_Reserve6 "预留数据";
CM_ SG_ 2149547901 D2P_ALARM_Reserve7 "预留数据";
CM_ SG_ 2149547901 D2P_ALARM_Reserve8 "预留数据";
CM_ SG_ 2149547901 D2P_ALARM_Reserve9 "预留数据";
CM_ SG_ 2149547901 D2P_ALARM_Reserve10 "预留数据";
CM_ SG_ 2149547901 D2P_ALARM_Reserve11 "预留数据";
CM_ SG_ 2149547902 D2P_ALARM_EnvExtreOverTemp "环境极限过温";
CM_ SG_ 2149547902 D2P_ALARM_EnvOverTemp "环境过温";
CM_ SG_ 2149547902 D2P_ALARM_MosOverTemp "MOS管过温";
CM_ SG_ 2149547902 D2P_ALARM_MosExtreOverTemp "MOS管极限过温";
CM_ SG_ 2149547902 D2P_ALARM_HighSideOverVolt "高压侧过压故障";
CM_ SG_ 2149547902 D2P_ALARM_HighSideUnderVolt "高压侧欠压故障";
CM_ SG_ 2149547902 D2P_ALARM_LowSideOverVolt "低压侧过压故障";
CM_ SG_ 2149547902 D2P_ALARM_HighSideOverCurr "高压侧过流故障";
CM_ SG_ 2149547902 D2P_ALARM_LowSideOverCurr_HW "低压侧硬件过流故障";
CM_ SG_ 2149547902 D2P_ALARM_LowSideOverCurr_SW "低压侧软件过流故障";
CM_ SG_ 2149547902 D2P_ALARM_SecSideOverCurr_HW "谐振腔副边硬件过流";
CM_ SG_ 2149547902 D2P_ALARM_SecSideOverCurr_SW "谐振腔副边软件过流";
CM_ SG_ 2149547902 D2P_ALARM_PriSideOverCurr_HW "谐振腔源边硬件过流";
CM_ SG_ 2149547902 D2P_ALARM_PriSideOverCurr_SW "谐振腔源边软件过流";
CM_ SG_ 2149547902 D2P_ALARM_LowPowerSupplyErr "低压电源供电异常";
CM_ SG_ 2149547902 D2P_ALARM_MBMUComErr "MBMU通讯故障";
CM_ SG_ 2149547902 D2P_ALARM_DCDCMsTeSaplgErr "DCDCMOS管采样温度异常（单点）";
CM_ SG_ 2149547902 D2P_ALARM_DCDCTeSaplgErr "DCDC温度采样异常（双点及以上)";
CM_ SG_ 2149547902 D2P_ALARM_VoltSamplingErr "电压采样异常";
CM_ SG_ 2149547902 D2P_ALARM_HgSdCuSaplgErr "高压侧电流采样异常";
CM_ SG_ 2149547902 D2P_ALARM_CtrlCurrSamplingErr "控制电流采样异常";
CM_ SG_ 2149547902 D2P_ALARM_BypassFail "切旁路失败";
CM_ SG_ 2149547902 D2P_ALARM_Reserve1 "预留数据";
CM_ SG_ 2149547902 D2P_ALARM_Reserve2 "预留数据";
CM_ SG_ 2149547902 D2P_ALARM_Reserve3 "预留数据";
CM_ SG_ 2149547902 D2P_ALARM_Reserve4 "预留数据";
CM_ SG_ 2149547902 D2P_ALARM_Reserve5 "预留数据";
CM_ SG_ 2149547902 D2P_ALARM_Reserve6 "预留数据";
CM_ SG_ 2149547902 D2P_ALARM_Reserve7 "预留数据";
CM_ SG_ 2149547902 D2P_ALARM_Reserve8 "预留数据";
CM_ SG_ 2149547902 D2P_ALARM_Reserve9 "预留数据";
CM_ SG_ 2149547902 D2P_ALARM_Reserve10 "预留数据";
CM_ SG_ 2149547902 D2P_ALARM_Reserve11 "预留数据";
CM_ SG_ 2149547903 D2P_ALARM_EnvExtreOverTemp "环境极限过温";
CM_ SG_ 2149547903 D2P_ALARM_EnvOverTemp "环境过温";
CM_ SG_ 2149547903 D2P_ALARM_MosOverTemp "MOS管过温";
CM_ SG_ 2149547903 D2P_ALARM_MosExtreOverTemp "MOS管极限过温";
CM_ SG_ 2149547903 D2P_ALARM_HighSideOverVolt "高压侧过压故障";
CM_ SG_ 2149547903 D2P_ALARM_HighSideUnderVolt "高压侧欠压故障";
CM_ SG_ 2149547903 D2P_ALARM_LowSideOverVolt "低压侧过压故障";
CM_ SG_ 2149547903 D2P_ALARM_HighSideOverCurr "高压侧过流故障";
CM_ SG_ 2149547903 D2P_ALARM_LowSideOverCurr_HW "低压侧硬件过流故障";
CM_ SG_ 2149547903 D2P_ALARM_LowSideOverCurr_SW "低压侧软件过流故障";
CM_ SG_ 2149547903 D2P_ALARM_SecSideOverCurr_HW "谐振腔副边硬件过流";
CM_ SG_ 2149547903 D2P_ALARM_SecSideOverCurr_SW "谐振腔副边软件过流";
CM_ SG_ 2149547903 D2P_ALARM_PriSideOverCurr_HW "谐振腔源边硬件过流";
CM_ SG_ 2149547903 D2P_ALARM_PriSideOverCurr_SW "谐振腔源边软件过流";
CM_ SG_ 2149547903 D2P_ALARM_LowPowerSupplyErr "低压电源供电异常";
CM_ SG_ 2149547903 D2P_ALARM_MBMUComErr "MBMU通讯故障";
CM_ SG_ 2149547903 D2P_ALARM_DCDCMsTeSaplgErr "DCDCMOS管采样温度异常（单点）";
CM_ SG_ 2149547903 D2P_ALARM_DCDCTeSaplgErr "DCDC温度采样异常（双点及以上)";
CM_ SG_ 2149547903 D2P_ALARM_VoltSamplingErr "电压采样异常";
CM_ SG_ 2149547903 D2P_ALARM_HgSdCuSaplgErr "高压侧电流采样异常";
CM_ SG_ 2149547903 D2P_ALARM_CtrlCurrSamplingErr "控制电流采样异常";
CM_ SG_ 2149547903 D2P_ALARM_BypassFail "切旁路失败";
CM_ SG_ 2149547903 D2P_ALARM_Reserve1 "预留数据";
CM_ SG_ 2149547903 D2P_ALARM_Reserve2 "预留数据";
CM_ SG_ 2149547903 D2P_ALARM_Reserve3 "预留数据";
CM_ SG_ 2149547903 D2P_ALARM_Reserve4 "预留数据";
CM_ SG_ 2149547903 D2P_ALARM_Reserve5 "预留数据";
CM_ SG_ 2149547903 D2P_ALARM_Reserve6 "预留数据";
CM_ SG_ 2149547903 D2P_ALARM_Reserve7 "预留数据";
CM_ SG_ 2149547903 D2P_ALARM_Reserve8 "预留数据";
CM_ SG_ 2149547903 D2P_ALARM_Reserve9 "预留数据";
CM_ SG_ 2149547903 D2P_ALARM_Reserve10 "预留数据";
CM_ SG_ 2149547903 D2P_ALARM_Reserve11 "预留数据";
CM_ SG_ 2334457665 Reserve "预留";
CM_ SG_ 2334457665 S2A_BAT_I_HVS_mA_01 "电柜采集电流(mA)";
CM_ SG_ 2334457666 Reserve "预留";
CM_ SG_ 2334457666 S2A_BAT_I_HVS_mA_02 "电柜采集电流(mA)";
CM_ SG_ 2334457667 Reserve "预留";
CM_ SG_ 2334457667 S2A_BAT_I_HVS_mA_03 "电柜采集电流(mA)";
CM_ SG_ 2334457668 Reserve "预留";
CM_ SG_ 2334457668 S2A_BAT_I_HVS_mA_04 "电柜采集电流(mA)";
CM_ SG_ 2334457669 Reserve "预留";
CM_ SG_ 2334457669 S2A_BAT_I_HVS_mA_05 "电柜采集电流(mA)";
CM_ SG_ 2334457670 Reserve "预留";
CM_ SG_ 2334457670 S2A_BAT_I_HVS_mA_06 "电柜采集电流(mA)";
CM_ SG_ 2334457671 Reserve "预留";
CM_ SG_ 2334457671 S2A_BAT_I_HVS_mA_07 "电柜采集电流(mA)";
CM_ SG_ 2334457672 Reserve "预留";
CM_ SG_ 2334457672 S2A_BAT_I_HVS_mA_08 "电柜采集电流(mA)";
CM_ SG_ 2334457673 Reserve "预留";
CM_ SG_ 2334457673 S2A_BAT_I_HVS_mA_09 "电柜采集电流(mA)";
CM_ SG_ 2334457674 Reserve "预留";
CM_ SG_ 2334457674 S2A_BAT_I_HVS_mA_10 "电柜采集电流(mA)";
CM_ SG_ 2334457675 Reserve "预留";
CM_ SG_ 2334457675 S2A_BAT_I_HVS_mA_11 "电柜采集电流(mA)";
CM_ SG_ 2334457676 Reserve "预留";
CM_ SG_ 2334457676 S2A_BAT_I_HVS_mA_12 "电柜采集电流(mA)";
CM_ SG_ 2334457677 Reserve "预留";
CM_ SG_ 2334457677 S2A_BAT_I_HVS_mA_13 "电柜采集电流(mA)";
CM_ SG_ 2334457678 Reserve "预留";
CM_ SG_ 2334457678 S2A_BAT_I_HVS_mA_14 "电柜采集电流(mA)";
CM_ SG_ 2334457679 Reserve "预留";
CM_ SG_ 2334457679 S2A_BAT_I_HVS_mA_15 "电柜采集电流(mA)";
CM_ SG_ 2334457680 Reserve "预留";
CM_ SG_ 2334457680 S2A_BAT_I_HVS_mA_16 "电柜采集电流(mA)";
CM_ SG_ 2334457681 Reserve "预留";
CM_ SG_ 2334457681 S2A_BAT_I_HVS_mA_17 "电柜采集电流(mA)";
CM_ SG_ 2334457682 Reserve "预留";
CM_ SG_ 2334457682 S2A_BAT_I_HVS_mA_18 "电柜采集电流(mA)";
CM_ SG_ 2334457683 Reserve "预留";
CM_ SG_ 2334457683 S2A_BAT_I_HVS_mA_19 "电柜采集电流(mA)";
CM_ SG_ 2334457684 Reserve "预留";
CM_ SG_ 2334457684 S2A_BAT_I_HVS_mA_20 "电柜采集电流(mA)";
CM_ SG_ 2334457685 Reserve "预留";
CM_ SG_ 2334457685 S2A_BAT_I_HVS_mA_21 "电柜采集电流(mA)";
CM_ SG_ 2334457686 Reserve "预留";
CM_ SG_ 2334457686 S2A_BAT_I_HVS_mA_22 "电柜采集电流(mA)";
CM_ SG_ 2334457687 Reserve "预留";
CM_ SG_ 2334457687 S2A_BAT_I_HVS_mA_23 "电柜采集电流(mA)";
CM_ SG_ 2334457688 Reserve "预留";
CM_ SG_ 2334457688 S2A_BAT_I_HVS_mA_24 "电柜采集电流(mA)";
CM_ SG_ 2334457689 Reserve "预留";
CM_ SG_ 2334457689 S2A_BAT_I_HVS_mA_25 "电柜采集电流(mA)";
CM_ SG_ 2334457690 Reserve "预留";
CM_ SG_ 2334457690 S2A_BAT_I_HVS_mA_26 "电柜采集电流(mA)";
CM_ SG_ 2334457691 Reserve "预留";
CM_ SG_ 2334457691 S2A_BAT_I_HVS_mA_27 "电柜采集电流(mA)";
CM_ SG_ 2334457692 Reserve "预留";
CM_ SG_ 2334457692 S2A_BAT_I_HVS_mA_28 "电柜采集电流(mA)";
CM_ SG_ 2334457693 Reserve "预留";
CM_ SG_ 2334457693 S2A_BAT_I_HVS_mA_29 "电柜采集电流(mA)";
CM_ SG_ 2334457694 Reserve "预留";
CM_ SG_ 2334457694 S2A_BAT_I_HVS_mA_30 "电柜采集电流(mA)";
CM_ SG_ 2334457695 Reserve "预留";
CM_ SG_ 2334457695 S2A_BAT_I_HVS_mA_31 "电柜采集电流(mA)";
CM_ SG_ 2334457696 Reserve "预留";
CM_ SG_ 2334457696 S2A_BAT_I_HVS_mA_32 "电柜采集电流(mA)";
CM_ SG_ 2334457697 Reserve "预留";
CM_ SG_ 2334457697 S2A_BAT_I_HVS_mA_33 "电柜采集电流(mA)";
CM_ SG_ 2334457698 Reserve "预留";
CM_ SG_ 2334457698 S2A_BAT_I_HVS_mA_34 "电柜采集电流(mA)";
CM_ SG_ 2334457699 Reserve "预留";
CM_ SG_ 2334457699 S2A_BAT_I_HVS_mA_35 "电柜采集电流(mA)";
CM_ SG_ 2334457700 Reserve "预留";
CM_ SG_ 2334457700 S2A_BAT_I_HVS_mA_36 "电柜采集电流(mA)";
CM_ SG_ 2334457701 Reserve "预留";
CM_ SG_ 2334457701 S2A_BAT_I_HVS_mA_37 "电柜采集电流(mA)";
CM_ SG_ 2334457702 Reserve "预留";
CM_ SG_ 2334457702 S2A_BAT_I_HVS_mA_38 "电柜采集电流(mA)";
CM_ SG_ 2334457703 Reserve "预留";
CM_ SG_ 2334457703 S2A_BAT_I_HVS_mA_39 "电柜采集电流(mA)";
CM_ SG_ 2334457704 Reserve "预留";
CM_ SG_ 2334457704 S2A_BAT_I_HVS_mA_40 "电柜采集电流(mA)";
CM_ SG_ 2334457705 Reserve "预留";
CM_ SG_ 2334457705 S2A_BAT_I_HVS_mA_41 "电柜采集电流(mA)";
CM_ SG_ 2334457706 Reserve "预留";
CM_ SG_ 2334457706 S2A_BAT_I_HVS_mA_42 "电柜采集电流(mA)";
CM_ SG_ 2334457707 Reserve "预留";
CM_ SG_ 2334457707 S2A_BAT_I_HVS_mA_43 "电柜采集电流(mA)";
CM_ SG_ 2334457708 Reserve "预留";
CM_ SG_ 2334457708 S2A_BAT_I_HVS_mA_44 "电柜采集电流(mA)";
CM_ SG_ 2334457709 Reserve "预留";
CM_ SG_ 2334457709 S2A_BAT_I_HVS_mA_45 "电柜采集电流(mA)";
CM_ SG_ 2334457710 Reserve "预留";
CM_ SG_ 2334457710 S2A_BAT_I_HVS_mA_46 "电柜采集电流(mA)";
CM_ SG_ 2334457711 Reserve "预留";
CM_ SG_ 2334457711 S2A_BAT_I_HVS_mA_47 "电柜采集电流(mA)";
CM_ SG_ 2334457712 Reserve "预留";
CM_ SG_ 2334457712 S2A_BAT_I_HVS_mA_48 "电柜采集电流(mA)";
CM_ SG_ 2334457713 Reserve "预留";
CM_ SG_ 2334457713 S2A_BAT_I_HVS_mA_49 "电柜采集电流(mA)";
CM_ SG_ 2334457714 Reserve "预留";
CM_ SG_ 2334457714 S2A_BAT_I_HVS_mA_50 "电柜采集电流(mA)";
CM_ SG_ 2334457715 Reserve "预留";
CM_ SG_ 2334457715 S2A_BAT_I_HVS_mA_51 "电柜采集电流(mA)";
CM_ SG_ 2334457716 Reserve "预留";
CM_ SG_ 2334457716 S2A_BAT_I_HVS_mA_52 "电柜采集电流(mA)";
CM_ SG_ 2334457717 Reserve "预留";
CM_ SG_ 2334457717 S2A_BAT_I_HVS_mA_53 "电柜采集电流(mA)";
CM_ SG_ 2334457718 Reserve "预留";
CM_ SG_ 2334457718 S2A_BAT_I_HVS_mA_54 "电柜采集电流(mA)";
CM_ SG_ 2334457719 Reserve "预留";
CM_ SG_ 2334457719 S2A_BAT_I_HVS_mA_55 "电柜采集电流(mA)";
CM_ SG_ 2334457720 Reserve "预留";
CM_ SG_ 2334457720 S2A_BAT_I_HVS_mA_56 "电柜采集电流(mA)";
CM_ SG_ 2334457721 Reserve "预留";
CM_ SG_ 2334457721 S2A_BAT_I_HVS_mA_57 "电柜采集电流(mA)";
CM_ SG_ 2334457722 Reserve "预留";
CM_ SG_ 2334457722 S2A_BAT_I_HVS_mA_58 "电柜采集电流(mA)";
CM_ SG_ 2334457723 Reserve "预留";
CM_ SG_ 2334457723 S2A_BAT_I_HVS_mA_59 "电柜采集电流(mA)";
CM_ SG_ 2334457724 Reserve "预留";
CM_ SG_ 2334457724 S2A_BAT_I_HVS_mA_60 "电柜采集电流(mA)";
CM_ SG_ 2334457725 Reserve "预留";
CM_ SG_ 2334457725 S2A_BAT_I_HVS_mA_61 "电柜采集电流(mA)";
CM_ SG_ 2334457726 Reserve "预留";
CM_ SG_ 2334457726 S2A_BAT_I_HVS_mA_62 "电柜采集电流(mA)";
CM_ SG_ 2334457727 Reserve "预留";
CM_ SG_ 2334457727 S2A_BAT_I_HVS_mA_63 "电柜采集电流(mA)";
CM_ SG_ 2467463087 M2Sd_IDX_CMD_Type "MBMU发送给SBMU/DCDC的自动编码命令类型";
CM_ SG_ 2467463087 M2SD_IDX_SD_Index "MBMU发送给SBMU/DCDC的编码地址";
CM_ SG_ 2467463087 M2SD_SD_MatchingCode "MBMU发送给SBMU/DCDC的匹配码";
CM_ SG_ 2467463087 M2SD_SD_Result "MBMU发送给SBMU/DCDC的编码结果";
CM_ SG_ 2467463087 Reserved_1 "预留1";
CM_ SG_ 2467475265 S2M_IDX_CMD_Type_01 "SBMU发送给MBMU的自动编码命令类型";
CM_ SG_ 2467475265 S2M_IDX_SBMU_Index_01 "SBMU发送给MBMU的SBMU的编码地址";
CM_ SG_ 2467475265 S2M_SBMU_MatchingCode_01 "SBMU发送给MBMU的SBMU的匹配码";
CM_ SG_ 2467475265 S2M_SBMU_Result_01 "SBMU发送给MBMU的编码结果/存储结果 ";
CM_ SG_ 2467475266 S2M_IDX_CMD_Type_02 "SBMU发送给MBMU的自动编码命令类型";
CM_ SG_ 2467475266 S2M_IDX_SBMU_Index_02 "SBMU发送给MBMU的SBMU的编码地址";
CM_ SG_ 2467475266 S2M_SBMU_MatchingCode_02 "SBMU发送给MBMU的SBMU的匹配码";
CM_ SG_ 2467475266 S2M_SBMU_Result_02 "SBMU发送给MBMU的编码结果/存储结果 ";
CM_ SG_ 2467475267 S2M_IDX_CMD_Type_03 "SBMU发送给MBMU的自动编码命令类型";
CM_ SG_ 2467475267 S2M_IDX_SBMU_Index_03 "SBMU发送给MBMU的SBMU的编码地址";
CM_ SG_ 2467475267 S2M_SBMU_MatchingCode_03 "SBMU发送给MBMU的SBMU的匹配码";
CM_ SG_ 2467475267 S2M_SBMU_Result_03 "SBMU发送给MBMU的编码结果/存储结果 ";
CM_ SG_ 2467475268 S2M_IDX_CMD_Type_04 "SBMU发送给MBMU的自动编码命令类型";
CM_ SG_ 2467475268 S2M_IDX_SBMU_Index_04 "SBMU发送给MBMU的SBMU的编码地址";
CM_ SG_ 2467475268 S2M_SBMU_MatchingCode_04 "SBMU发送给MBMU的SBMU的匹配码";
CM_ SG_ 2467475268 S2M_SBMU_Result_04 "SBMU发送给MBMU的编码结果/存储结果 ";
CM_ SG_ 2467475269 S2M_IDX_CMD_Type_05 "SBMU发送给MBMU的自动编码命令类型";
CM_ SG_ 2467475269 S2M_IDX_SBMU_Index_05 "SBMU发送给MBMU的SBMU的编码地址";
CM_ SG_ 2467475269 S2M_SBMU_MatchingCode_05 "SBMU发送给MBMU的SBMU的匹配码";
CM_ SG_ 2467475269 S2M_SBMU_Result_05 "SBMU发送给MBMU的编码结果/存储结果 ";
CM_ SG_ 2467475270 S2M_IDX_CMD_Type_06 "SBMU发送给MBMU的自动编码命令类型";
CM_ SG_ 2467475270 S2M_IDX_SBMU_Index_06 "SBMU发送给MBMU的SBMU的编码地址";
CM_ SG_ 2467475270 S2M_SBMU_MatchingCode_06 "SBMU发送给MBMU的SBMU的匹配码";
CM_ SG_ 2467475270 S2M_SBMU_Result_06 "SBMU发送给MBMU的编码结果/存储结果 ";
CM_ SG_ 2467475271 S2M_IDX_CMD_Type_07 "SBMU发送给MBMU的自动编码命令类型";
CM_ SG_ 2467475271 S2M_IDX_SBMU_Index_07 "SBMU发送给MBMU的SBMU的编码地址";
CM_ SG_ 2467475271 S2M_SBMU_MatchingCode_07 "SBMU发送给MBMU的SBMU的匹配码";
CM_ SG_ 2467475271 S2M_SBMU_Result_07 "SBMU发送给MBMU的编码结果/存储结果 ";
CM_ SG_ 2467475272 S2M_IDX_CMD_Type_08 "SBMU发送给MBMU的自动编码命令类型";
CM_ SG_ 2467475272 S2M_IDX_SBMU_Index_08 "SBMU发送给MBMU的SBMU的编码地址";
CM_ SG_ 2467475272 S2M_SBMU_MatchingCode_08 "SBMU发送给MBMU的SBMU的匹配码";
CM_ SG_ 2467475272 S2M_SBMU_Result_08 "SBMU发送给MBMU的编码结果/存储结果 ";
CM_ SG_ 2467475273 S2M_IDX_CMD_Type_09 "SBMU发送给MBMU的自动编码命令类型";
CM_ SG_ 2467475273 S2M_IDX_SBMU_Index_09 "SBMU发送给MBMU的SBMU的编码地址";
CM_ SG_ 2467475273 S2M_SBMU_MatchingCode_09 "SBMU发送给MBMU的SBMU的匹配码";
CM_ SG_ 2467475273 S2M_SBMU_Result_09 "SBMU发送给MBMU的编码结果/存储结果 ";
CM_ SG_ 2467475274 S2M_IDX_CMD_Type_10 "SBMU发送给MBMU的自动编码命令类型";
CM_ SG_ 2467475274 S2M_IDX_SBMU_Index_10 "SBMU发送给MBMU的SBMU的编码地址";
CM_ SG_ 2467475274 S2M_SBMU_MatchingCode_10 "SBMU发送给MBMU的SBMU的匹配码";
CM_ SG_ 2467475274 S2M_SBMU_Result_10 "SBMU发送给MBMU的编码结果/存储结果 ";
CM_ SG_ 2467475275 S2M_IDX_CMD_Type_11 "SBMU发送给MBMU的自动编码命令类型";
CM_ SG_ 2467475275 S2M_IDX_SBMU_Index_11 "SBMU发送给MBMU的SBMU的编码地址";
CM_ SG_ 2467475275 S2M_SBMU_MatchingCode_11 "SBMU发送给MBMU的SBMU的匹配码";
CM_ SG_ 2467475275 S2M_SBMU_Result_11 "SBMU发送给MBMU的编码结果/存储结果 ";
CM_ SG_ 2467475276 S2M_IDX_CMD_Type_12 "SBMU发送给MBMU的自动编码命令类型";
CM_ SG_ 2467475276 S2M_IDX_SBMU_Index_12 "SBMU发送给MBMU的SBMU的编码地址";
CM_ SG_ 2467475276 S2M_SBMU_MatchingCode_12 "SBMU发送给MBMU的SBMU的匹配码";
CM_ SG_ 2467475276 S2M_SBMU_Result_12 "SBMU发送给MBMU的编码结果/存储结果 ";
CM_ SG_ 2467475277 S2M_IDX_CMD_Type_13 "SBMU发送给MBMU的自动编码命令类型";
CM_ SG_ 2467475277 S2M_IDX_SBMU_Index_13 "SBMU发送给MBMU的SBMU的编码地址";
CM_ SG_ 2467475277 S2M_SBMU_MatchingCode_13 "SBMU发送给MBMU的SBMU的匹配码";
CM_ SG_ 2467475277 S2M_SBMU_Result_13 "SBMU发送给MBMU的编码结果/存储结果 ";
CM_ SG_ 2467475278 S2M_IDX_CMD_Type_14 "SBMU发送给MBMU的自动编码命令类型";
CM_ SG_ 2467475278 S2M_IDX_SBMU_Index_14 "SBMU发送给MBMU的SBMU的编码地址";
CM_ SG_ 2467475278 S2M_SBMU_MatchingCode_14 "SBMU发送给MBMU的SBMU的匹配码";
CM_ SG_ 2467475278 S2M_SBMU_Result_14 "SBMU发送给MBMU的编码结果/存储结果 ";
CM_ SG_ 2467475279 S2M_IDX_CMD_Type_15 "SBMU发送给MBMU的自动编码命令类型";
CM_ SG_ 2467475279 S2M_IDX_SBMU_Index_15 "SBMU发送给MBMU的SBMU的编码地址";
CM_ SG_ 2467475279 S2M_SBMU_MatchingCode_15 "SBMU发送给MBMU的SBMU的匹配码";
CM_ SG_ 2467475279 S2M_SBMU_Result_15 "SBMU发送给MBMU的编码结果/存储结果 ";
CM_ SG_ 2467475280 S2M_IDX_CMD_Type_16 "SBMU发送给MBMU的自动编码命令类型";
CM_ SG_ 2467475280 S2M_IDX_SBMU_Index_16 "SBMU发送给MBMU的SBMU的编码地址";
CM_ SG_ 2467475280 S2M_SBMU_MatchingCode_16 "SBMU发送给MBMU的SBMU的匹配码";
CM_ SG_ 2467475280 S2M_SBMU_Result_16 "SBMU发送给MBMU的编码结果/存储结果 ";
VAL_ 2149547879 D2P_ALARM_EnvExtreOverTemp 0 "No Alarm" 1 "Alarm Occur" ;
VAL_ 2149547879 D2P_ALARM_EnvOverTemp 0 "No Alarm" 1 "Alarm Occur" ;
VAL_ 2149547879 D2P_ALARM_MosOverTemp 0 "No Alarm" 1 "Alarm Occur" ;
VAL_ 2149547879 D2P_ALARM_MosExtreOverTemp 0 "No Alarm" 1 "Alarm Occur" ;
VAL_ 2149547879 D2P_ALARM_HighSideOverVolt 0 "No Alarm" 1 "Alarm Occur" ;
VAL_ 2149547879 D2P_ALARM_HighSideUnderVolt 0 "No Alarm" 1 "Alarm Occur" ;
VAL_ 2149547879 D2P_ALARM_LowSideOverVolt 0 "No Alarm" 1 "Alarm Occur" ;
VAL_ 2149547879 D2P_ALARM_HighSideOverCurr 0 "No Alarm" 1 "Alarm Occur" ;
VAL_ 2149547879 D2P_ALARM_LowSideOverCurr_HW 0 "No Alarm" 1 "Alarm Occur" ;
VAL_ 2149547879 D2P_ALARM_LowSideOverCurr_SW 0 "No Alarm" 1 "Alarm Occur" ;
VAL_ 2149547879 D2P_ALARM_SecSideOverCurr_HW 0 "No Alarm" 1 "Alarm Occur" ;
VAL_ 2149547879 D2P_ALARM_SecSideOverCurr_SW 0 "No Alarm" 1 "Alarm Occur" ;
VAL_ 2149547879 D2P_ALARM_PriSideOverCurr_HW 0 "No Alarm" 1 "Alarm Occur" ;
VAL_ 2149547879 D2P_ALARM_PriSideOverCurr_SW 0 "No Alarm" 1 "Alarm Occur" ;
VAL_ 2149547879 D2P_ALARM_LowPowerSupplyErr 0 "No Alarm" 1 "Alarm Occur" ;
VAL_ 2149547879 D2P_ALARM_MBMUComErr 0 "No Alarm" 1 "Alarm Occur" ;
VAL_ 2149547879 D2P_ALARM_DCDCMsTeSaplgErr 0 "No Alarm" 1 "Alarm Occur" ;
VAL_ 2149547879 D2P_ALARM_DCDCTeSaplgErr 0 "No Alarm" 1 "Alarm Occur" ;
VAL_ 2149547879 D2P_ALARM_VoltSamplingErr 0 "No Alarm" 1 "Alarm Occur" ;
VAL_ 2149547879 D2P_ALARM_HgSdCuSaplgErr 0 "No Alarm" 1 "Alarm Occur" ;
VAL_ 2149547879 D2P_ALARM_CtrlCurrSamplingErr 0 "No Alarm" 1 "Alarm Occur" ;
VAL_ 2149547879 D2P_ALARM_BypassFail 0 "No Alarm" 1 "Alarm Occur" ;
VAL_ 2149547879 D2P_ALARM_Reserve1 0 "No Alarm" 1 "Alarm Occur" ;
VAL_ 2149547879 D2P_ALARM_Reserve2 0 "No Alarm" 1 "Alarm Occur" ;
VAL_ 2149547879 D2P_ALARM_Reserve3 0 "No Alarm" 1 "Alarm Occur" ;
VAL_ 2149547879 D2P_ALARM_Reserve4 0 "No Alarm" 1 "Alarm Occur" ;
VAL_ 2149547879 D2P_ALARM_Reserve5 0 "No Alarm" 1 "Alarm Occur" ;
VAL_ 2149547879 D2P_ALARM_Reserve6 0 "No Alarm" 1 "Alarm Occur" ;
VAL_ 2149547879 D2P_ALARM_Reserve7 0 "No Alarm" 1 "Alarm Occur" ;
VAL_ 2149547879 D2P_ALARM_Reserve8 0 "No Alarm" 1 "Alarm Occur" ;
VAL_ 2149547879 D2P_ALARM_Reserve9 0 "No Alarm" 1 "Alarm Occur" ;
VAL_ 2149547879 D2P_ALARM_Reserve10 0 "No Alarm" 1 "Alarm Occur" ;
VAL_ 2149547879 D2P_ALARM_Reserve11 0 "No Alarm" 1 "Alarm Occur" ;
VAL_ 2149547880 D2P_ALARM_EnvExtreOverTemp 0 "No Alarm" 1 "Alarm Occur" ;
VAL_ 2149547880 D2P_ALARM_EnvOverTemp 0 "No Alarm" 1 "Alarm Occur" ;
VAL_ 2149547880 D2P_ALARM_MosOverTemp 0 "No Alarm" 1 "Alarm Occur" ;
VAL_ 2149547880 D2P_ALARM_MosExtreOverTemp 0 "No Alarm" 1 "Alarm Occur" ;
VAL_ 2149547880 D2P_ALARM_HighSideOverVolt 0 "No Alarm" 1 "Alarm Occur" ;
VAL_ 2149547880 D2P_ALARM_HighSideUnderVolt 0 "No Alarm" 1 "Alarm Occur" ;
VAL_ 2149547880 D2P_ALARM_LowSideOverVolt 0 "No Alarm" 1 "Alarm Occur" ;
VAL_ 2149547880 D2P_ALARM_HighSideOverCurr 0 "No Alarm" 1 "Alarm Occur" ;
VAL_ 2149547880 D2P_ALARM_LowSideOverCurr_HW 0 "No Alarm" 1 "Alarm Occur" ;
VAL_ 2149547880 D2P_ALARM_LowSideOverCurr_SW 0 "No Alarm" 1 "Alarm Occur" ;
VAL_ 2149547880 D2P_ALARM_SecSideOverCurr_HW 0 "No Alarm" 1 "Alarm Occur" ;
VAL_ 2149547880 D2P_ALARM_SecSideOverCurr_SW 0 "No Alarm" 1 "Alarm Occur" ;
VAL_ 2149547880 D2P_ALARM_PriSideOverCurr_HW 0 "No Alarm" 1 "Alarm Occur" ;
VAL_ 2149547880 D2P_ALARM_PriSideOverCurr_SW 0 "No Alarm" 1 "Alarm Occur" ;
VAL_ 2149547880 D2P_ALARM_LowPowerSupplyErr 0 "No Alarm" 1 "Alarm Occur" ;
VAL_ 2149547880 D2P_ALARM_MBMUComErr 0 "No Alarm" 1 "Alarm Occur" ;
VAL_ 2149547880 D2P_ALARM_DCDCMsTeSaplgErr 0 "No Alarm" 1 "Alarm Occur" ;
VAL_ 2149547880 D2P_ALARM_DCDCTeSaplgErr 0 "No Alarm" 1 "Alarm Occur" ;
VAL_ 2149547880 D2P_ALARM_VoltSamplingErr 0 "No Alarm" 1 "Alarm Occur" ;
VAL_ 2149547880 D2P_ALARM_HgSdCuSaplgErr 0 "No Alarm" 1 "Alarm Occur" ;
VAL_ 2149547880 D2P_ALARM_CtrlCurrSamplingErr 0 "No Alarm" 1 "Alarm Occur" ;
VAL_ 2149547880 D2P_ALARM_BypassFail 0 "No Alarm" 1 "Alarm Occur" ;
VAL_ 2149547880 D2P_ALARM_Reserve1 0 "No Alarm" 1 "Alarm Occur" ;
VAL_ 2149547880 D2P_ALARM_Reserve2 0 "No Alarm" 1 "Alarm Occur" ;
VAL_ 2149547880 D2P_ALARM_Reserve3 0 "No Alarm" 1 "Alarm Occur" ;
VAL_ 2149547880 D2P_ALARM_Reserve4 0 "No Alarm" 1 "Alarm Occur" ;
VAL_ 2149547880 D2P_ALARM_Reserve5 0 "No Alarm" 1 "Alarm Occur" ;
VAL_ 2149547880 D2P_ALARM_Reserve6 0 "No Alarm" 1 "Alarm Occur" ;
VAL_ 2149547880 D2P_ALARM_Reserve7 0 "No Alarm" 1 "Alarm Occur" ;
VAL_ 2149547880 D2P_ALARM_Reserve8 0 "No Alarm" 1 "Alarm Occur" ;
VAL_ 2149547880 D2P_ALARM_Reserve9 0 "No Alarm" 1 "Alarm Occur" ;
VAL_ 2149547880 D2P_ALARM_Reserve10 0 "No Alarm" 1 "Alarm Occur" ;
VAL_ 2149547880 D2P_ALARM_Reserve11 0 "No Alarm" 1 "Alarm Occur" ;
VAL_ 2149547881 D2P_ALARM_EnvExtreOverTemp 0 "No Alarm" 1 "Alarm Occur" ;
VAL_ 2149547881 D2P_ALARM_EnvOverTemp 0 "No Alarm" 1 "Alarm Occur" ;
VAL_ 2149547881 D2P_ALARM_MosOverTemp 0 "No Alarm" 1 "Alarm Occur" ;
VAL_ 2149547881 D2P_ALARM_MosExtreOverTemp 0 "No Alarm" 1 "Alarm Occur" ;
VAL_ 2149547881 D2P_ALARM_HighSideOverVolt 0 "No Alarm" 1 "Alarm Occur" ;
VAL_ 2149547881 D2P_ALARM_HighSideUnderVolt 0 "No Alarm" 1 "Alarm Occur" ;
VAL_ 2149547881 D2P_ALARM_LowSideOverVolt 0 "No Alarm" 1 "Alarm Occur" ;
VAL_ 2149547881 D2P_ALARM_HighSideOverCurr 0 "No Alarm" 1 "Alarm Occur" ;
VAL_ 2149547881 D2P_ALARM_LowSideOverCurr_HW 0 "No Alarm" 1 "Alarm Occur" ;
VAL_ 2149547881 D2P_ALARM_LowSideOverCurr_SW 0 "No Alarm" 1 "Alarm Occur" ;
VAL_ 2149547881 D2P_ALARM_SecSideOverCurr_HW 0 "No Alarm" 1 "Alarm Occur" ;
VAL_ 2149547881 D2P_ALARM_SecSideOverCurr_SW 0 "No Alarm" 1 "Alarm Occur" ;
VAL_ 2149547881 D2P_ALARM_PriSideOverCurr_HW 0 "No Alarm" 1 "Alarm Occur" ;
VAL_ 2149547881 D2P_ALARM_PriSideOverCurr_SW 0 "No Alarm" 1 "Alarm Occur" ;
VAL_ 2149547881 D2P_ALARM_LowPowerSupplyErr 0 "No Alarm" 1 "Alarm Occur" ;
VAL_ 2149547881 D2P_ALARM_MBMUComErr 0 "No Alarm" 1 "Alarm Occur" ;
VAL_ 2149547881 D2P_ALARM_DCDCMsTeSaplgErr 0 "No Alarm" 1 "Alarm Occur" ;
VAL_ 2149547881 D2P_ALARM_DCDCTeSaplgErr 0 "No Alarm" 1 "Alarm Occur" ;
VAL_ 2149547881 D2P_ALARM_VoltSamplingErr 0 "No Alarm" 1 "Alarm Occur" ;
VAL_ 2149547881 D2P_ALARM_HgSdCuSaplgErr 0 "No Alarm" 1 "Alarm Occur" ;
VAL_ 2149547881 D2P_ALARM_CtrlCurrSamplingErr 0 "No Alarm" 1 "Alarm Occur" ;
VAL_ 2149547881 D2P_ALARM_BypassFail 0 "No Alarm" 1 "Alarm Occur" ;
VAL_ 2149547881 D2P_ALARM_Reserve1 0 "No Alarm" 1 "Alarm Occur" ;
VAL_ 2149547881 D2P_ALARM_Reserve2 0 "No Alarm" 1 "Alarm Occur" ;
VAL_ 2149547881 D2P_ALARM_Reserve3 0 "No Alarm" 1 "Alarm Occur" ;
VAL_ 2149547881 D2P_ALARM_Reserve4 0 "No Alarm" 1 "Alarm Occur" ;
VAL_ 2149547881 D2P_ALARM_Reserve5 0 "No Alarm" 1 "Alarm Occur" ;
VAL_ 2149547881 D2P_ALARM_Reserve6 0 "No Alarm" 1 "Alarm Occur" ;
VAL_ 2149547881 D2P_ALARM_Reserve7 0 "No Alarm" 1 "Alarm Occur" ;
VAL_ 2149547881 D2P_ALARM_Reserve8 0 "No Alarm" 1 "Alarm Occur" ;
VAL_ 2149547881 D2P_ALARM_Reserve9 0 "No Alarm" 1 "Alarm Occur" ;
VAL_ 2149547881 D2P_ALARM_Reserve10 0 "No Alarm" 1 "Alarm Occur" ;
VAL_ 2149547881 D2P_ALARM_Reserve11 0 "No Alarm" 1 "Alarm Occur" ;
VAL_ 2149547882 D2P_ALARM_EnvExtreOverTemp 0 "No Alarm" 1 "Alarm Occur" ;
VAL_ 2149547882 D2P_ALARM_EnvOverTemp 0 "No Alarm" 1 "Alarm Occur" ;
VAL_ 2149547882 D2P_ALARM_MosOverTemp 0 "No Alarm" 1 "Alarm Occur" ;
VAL_ 2149547882 D2P_ALARM_MosExtreOverTemp 0 "No Alarm" 1 "Alarm Occur" ;
VAL_ 2149547882 D2P_ALARM_HighSideOverVolt 0 "No Alarm" 1 "Alarm Occur" ;
VAL_ 2149547882 D2P_ALARM_HighSideUnderVolt 0 "No Alarm" 1 "Alarm Occur" ;
VAL_ 2149547882 D2P_ALARM_LowSideOverVolt 0 "No Alarm" 1 "Alarm Occur" ;
VAL_ 2149547882 D2P_ALARM_HighSideOverCurr 0 "No Alarm" 1 "Alarm Occur" ;
VAL_ 2149547882 D2P_ALARM_LowSideOverCurr_HW 0 "No Alarm" 1 "Alarm Occur" ;
VAL_ 2149547882 D2P_ALARM_LowSideOverCurr_SW 0 "No Alarm" 1 "Alarm Occur" ;
VAL_ 2149547882 D2P_ALARM_SecSideOverCurr_HW 0 "No Alarm" 1 "Alarm Occur" ;
VAL_ 2149547882 D2P_ALARM_SecSideOverCurr_SW 0 "No Alarm" 1 "Alarm Occur" ;
VAL_ 2149547882 D2P_ALARM_PriSideOverCurr_HW 0 "No Alarm" 1 "Alarm Occur" ;
VAL_ 2149547882 D2P_ALARM_PriSideOverCurr_SW 0 "No Alarm" 1 "Alarm Occur" ;
VAL_ 2149547882 D2P_ALARM_LowPowerSupplyErr 0 "No Alarm" 1 "Alarm Occur" ;
VAL_ 2149547882 D2P_ALARM_MBMUComErr 0 "No Alarm" 1 "Alarm Occur" ;
VAL_ 2149547882 D2P_ALARM_DCDCMsTeSaplgErr 0 "No Alarm" 1 "Alarm Occur" ;
VAL_ 2149547882 D2P_ALARM_DCDCTeSaplgErr 0 "No Alarm" 1 "Alarm Occur" ;
VAL_ 2149547882 D2P_ALARM_VoltSamplingErr 0 "No Alarm" 1 "Alarm Occur" ;
VAL_ 2149547882 D2P_ALARM_HgSdCuSaplgErr 0 "No Alarm" 1 "Alarm Occur" ;
VAL_ 2149547882 D2P_ALARM_CtrlCurrSamplingErr 0 "No Alarm" 1 "Alarm Occur" ;
VAL_ 2149547882 D2P_ALARM_BypassFail 0 "No Alarm" 1 "Alarm Occur" ;
VAL_ 2149547882 D2P_ALARM_Reserve1 0 "No Alarm" 1 "Alarm Occur" ;
VAL_ 2149547882 D2P_ALARM_Reserve2 0 "No Alarm" 1 "Alarm Occur" ;
VAL_ 2149547882 D2P_ALARM_Reserve3 0 "No Alarm" 1 "Alarm Occur" ;
VAL_ 2149547882 D2P_ALARM_Reserve4 0 "No Alarm" 1 "Alarm Occur" ;
VAL_ 2149547882 D2P_ALARM_Reserve5 0 "No Alarm" 1 "Alarm Occur" ;
VAL_ 2149547882 D2P_ALARM_Reserve6 0 "No Alarm" 1 "Alarm Occur" ;
VAL_ 2149547882 D2P_ALARM_Reserve7 0 "No Alarm" 1 "Alarm Occur" ;
VAL_ 2149547882 D2P_ALARM_Reserve8 0 "No Alarm" 1 "Alarm Occur" ;
VAL_ 2149547882 D2P_ALARM_Reserve9 0 "No Alarm" 1 "Alarm Occur" ;
VAL_ 2149547882 D2P_ALARM_Reserve10 0 "No Alarm" 1 "Alarm Occur" ;
VAL_ 2149547882 D2P_ALARM_Reserve11 0 "No Alarm" 1 "Alarm Occur" ;
VAL_ 2149547883 D2P_ALARM_EnvExtreOverTemp 0 "No Alarm" 1 "Alarm Occur" ;
VAL_ 2149547883 D2P_ALARM_EnvOverTemp 0 "No Alarm" 1 "Alarm Occur" ;
VAL_ 2149547883 D2P_ALARM_MosOverTemp 0 "No Alarm" 1 "Alarm Occur" ;
VAL_ 2149547883 D2P_ALARM_MosExtreOverTemp 0 "No Alarm" 1 "Alarm Occur" ;
VAL_ 2149547883 D2P_ALARM_HighSideOverVolt 0 "No Alarm" 1 "Alarm Occur" ;
VAL_ 2149547883 D2P_ALARM_HighSideUnderVolt 0 "No Alarm" 1 "Alarm Occur" ;
VAL_ 2149547883 D2P_ALARM_LowSideOverVolt 0 "No Alarm" 1 "Alarm Occur" ;
VAL_ 2149547883 D2P_ALARM_HighSideOverCurr 0 "No Alarm" 1 "Alarm Occur" ;
VAL_ 2149547883 D2P_ALARM_LowSideOverCurr_HW 0 "No Alarm" 1 "Alarm Occur" ;
VAL_ 2149547883 D2P_ALARM_LowSideOverCurr_SW 0 "No Alarm" 1 "Alarm Occur" ;
VAL_ 2149547883 D2P_ALARM_SecSideOverCurr_HW 0 "No Alarm" 1 "Alarm Occur" ;
VAL_ 2149547883 D2P_ALARM_SecSideOverCurr_SW 0 "No Alarm" 1 "Alarm Occur" ;
VAL_ 2149547883 D2P_ALARM_PriSideOverCurr_HW 0 "No Alarm" 1 "Alarm Occur" ;
VAL_ 2149547883 D2P_ALARM_PriSideOverCurr_SW 0 "No Alarm" 1 "Alarm Occur" ;
VAL_ 2149547883 D2P_ALARM_LowPowerSupplyErr 0 "No Alarm" 1 "Alarm Occur" ;
VAL_ 2149547883 D2P_ALARM_MBMUComErr 0 "No Alarm" 1 "Alarm Occur" ;
VAL_ 2149547883 D2P_ALARM_DCDCMsTeSaplgErr 0 "No Alarm" 1 "Alarm Occur" ;
VAL_ 2149547883 D2P_ALARM_DCDCTeSaplgErr 0 "No Alarm" 1 "Alarm Occur" ;
VAL_ 2149547883 D2P_ALARM_VoltSamplingErr 0 "No Alarm" 1 "Alarm Occur" ;
VAL_ 2149547883 D2P_ALARM_HgSdCuSaplgErr 0 "No Alarm" 1 "Alarm Occur" ;
VAL_ 2149547883 D2P_ALARM_CtrlCurrSamplingErr 0 "No Alarm" 1 "Alarm Occur" ;
VAL_ 2149547883 D2P_ALARM_BypassFail 0 "No Alarm" 1 "Alarm Occur" ;
VAL_ 2149547883 D2P_ALARM_Reserve1 0 "No Alarm" 1 "Alarm Occur" ;
VAL_ 2149547883 D2P_ALARM_Reserve2 0 "No Alarm" 1 "Alarm Occur" ;
VAL_ 2149547883 D2P_ALARM_Reserve3 0 "No Alarm" 1 "Alarm Occur" ;
VAL_ 2149547883 D2P_ALARM_Reserve4 0 "No Alarm" 1 "Alarm Occur" ;
VAL_ 2149547883 D2P_ALARM_Reserve5 0 "No Alarm" 1 "Alarm Occur" ;
VAL_ 2149547883 D2P_ALARM_Reserve6 0 "No Alarm" 1 "Alarm Occur" ;
VAL_ 2149547883 D2P_ALARM_Reserve7 0 "No Alarm" 1 "Alarm Occur" ;
VAL_ 2149547883 D2P_ALARM_Reserve8 0 "No Alarm" 1 "Alarm Occur" ;
VAL_ 2149547883 D2P_ALARM_Reserve9 0 "No Alarm" 1 "Alarm Occur" ;
VAL_ 2149547883 D2P_ALARM_Reserve10 0 "No Alarm" 1 "Alarm Occur" ;
VAL_ 2149547883 D2P_ALARM_Reserve11 0 "No Alarm" 1 "Alarm Occur" ;
VAL_ 2149547884 D2P_ALARM_EnvExtreOverTemp 0 "No Alarm" 1 "Alarm Occur" ;
VAL_ 2149547884 D2P_ALARM_EnvOverTemp 0 "No Alarm" 1 "Alarm Occur" ;
VAL_ 2149547884 D2P_ALARM_MosOverTemp 0 "No Alarm" 1 "Alarm Occur" ;
VAL_ 2149547884 D2P_ALARM_MosExtreOverTemp 0 "No Alarm" 1 "Alarm Occur" ;
VAL_ 2149547884 D2P_ALARM_HighSideOverVolt 0 "No Alarm" 1 "Alarm Occur" ;
VAL_ 2149547884 D2P_ALARM_HighSideUnderVolt 0 "No Alarm" 1 "Alarm Occur" ;
VAL_ 2149547884 D2P_ALARM_LowSideOverVolt 0 "No Alarm" 1 "Alarm Occur" ;
VAL_ 2149547884 D2P_ALARM_HighSideOverCurr 0 "No Alarm" 1 "Alarm Occur" ;
VAL_ 2149547884 D2P_ALARM_LowSideOverCurr_HW 0 "No Alarm" 1 "Alarm Occur" ;
VAL_ 2149547884 D2P_ALARM_LowSideOverCurr_SW 0 "No Alarm" 1 "Alarm Occur" ;
VAL_ 2149547884 D2P_ALARM_SecSideOverCurr_HW 0 "No Alarm" 1 "Alarm Occur" ;
VAL_ 2149547884 D2P_ALARM_SecSideOverCurr_SW 0 "No Alarm" 1 "Alarm Occur" ;
VAL_ 2149547884 D2P_ALARM_PriSideOverCurr_HW 0 "No Alarm" 1 "Alarm Occur" ;
VAL_ 2149547884 D2P_ALARM_PriSideOverCurr_SW 0 "No Alarm" 1 "Alarm Occur" ;
VAL_ 2149547884 D2P_ALARM_LowPowerSupplyErr 0 "No Alarm" 1 "Alarm Occur" ;
VAL_ 2149547884 D2P_ALARM_MBMUComErr 0 "No Alarm" 1 "Alarm Occur" ;
VAL_ 2149547884 D2P_ALARM_DCDCMsTeSaplgErr 0 "No Alarm" 1 "Alarm Occur" ;
VAL_ 2149547884 D2P_ALARM_DCDCTeSaplgErr 0 "No Alarm" 1 "Alarm Occur" ;
VAL_ 2149547884 D2P_ALARM_VoltSamplingErr 0 "No Alarm" 1 "Alarm Occur" ;
VAL_ 2149547884 D2P_ALARM_HgSdCuSaplgErr 0 "No Alarm" 1 "Alarm Occur" ;
VAL_ 2149547884 D2P_ALARM_CtrlCurrSamplingErr 0 "No Alarm" 1 "Alarm Occur" ;
VAL_ 2149547884 D2P_ALARM_BypassFail 0 "No Alarm" 1 "Alarm Occur" ;
VAL_ 2149547884 D2P_ALARM_Reserve1 0 "No Alarm" 1 "Alarm Occur" ;
VAL_ 2149547884 D2P_ALARM_Reserve2 0 "No Alarm" 1 "Alarm Occur" ;
VAL_ 2149547884 D2P_ALARM_Reserve3 0 "No Alarm" 1 "Alarm Occur" ;
VAL_ 2149547884 D2P_ALARM_Reserve4 0 "No Alarm" 1 "Alarm Occur" ;
VAL_ 2149547884 D2P_ALARM_Reserve5 0 "No Alarm" 1 "Alarm Occur" ;
VAL_ 2149547884 D2P_ALARM_Reserve6 0 "No Alarm" 1 "Alarm Occur" ;
VAL_ 2149547884 D2P_ALARM_Reserve7 0 "No Alarm" 1 "Alarm Occur" ;
VAL_ 2149547884 D2P_ALARM_Reserve8 0 "No Alarm" 1 "Alarm Occur" ;
VAL_ 2149547884 D2P_ALARM_Reserve9 0 "No Alarm" 1 "Alarm Occur" ;
VAL_ 2149547884 D2P_ALARM_Reserve10 0 "No Alarm" 1 "Alarm Occur" ;
VAL_ 2149547884 D2P_ALARM_Reserve11 0 "No Alarm" 1 "Alarm Occur" ;
VAL_ 2149547885 D2P_ALARM_EnvExtreOverTemp 0 "No Alarm" 1 "Alarm Occur" ;
VAL_ 2149547885 D2P_ALARM_EnvOverTemp 0 "No Alarm" 1 "Alarm Occur" ;
VAL_ 2149547885 D2P_ALARM_MosOverTemp 0 "No Alarm" 1 "Alarm Occur" ;
VAL_ 2149547885 D2P_ALARM_MosExtreOverTemp 0 "No Alarm" 1 "Alarm Occur" ;
VAL_ 2149547885 D2P_ALARM_HighSideOverVolt 0 "No Alarm" 1 "Alarm Occur" ;
VAL_ 2149547885 D2P_ALARM_HighSideUnderVolt 0 "No Alarm" 1 "Alarm Occur" ;
VAL_ 2149547885 D2P_ALARM_LowSideOverVolt 0 "No Alarm" 1 "Alarm Occur" ;
VAL_ 2149547885 D2P_ALARM_HighSideOverCurr 0 "No Alarm" 1 "Alarm Occur" ;
VAL_ 2149547885 D2P_ALARM_LowSideOverCurr_HW 0 "No Alarm" 1 "Alarm Occur" ;
VAL_ 2149547885 D2P_ALARM_LowSideOverCurr_SW 0 "No Alarm" 1 "Alarm Occur" ;
VAL_ 2149547885 D2P_ALARM_SecSideOverCurr_HW 0 "No Alarm" 1 "Alarm Occur" ;
VAL_ 2149547885 D2P_ALARM_SecSideOverCurr_SW 0 "No Alarm" 1 "Alarm Occur" ;
VAL_ 2149547885 D2P_ALARM_PriSideOverCurr_HW 0 "No Alarm" 1 "Alarm Occur" ;
VAL_ 2149547885 D2P_ALARM_PriSideOverCurr_SW 0 "No Alarm" 1 "Alarm Occur" ;
VAL_ 2149547885 D2P_ALARM_LowPowerSupplyErr 0 "No Alarm" 1 "Alarm Occur" ;
VAL_ 2149547885 D2P_ALARM_MBMUComErr 0 "No Alarm" 1 "Alarm Occur" ;
VAL_ 2149547885 D2P_ALARM_DCDCMsTeSaplgErr 0 "No Alarm" 1 "Alarm Occur" ;
VAL_ 2149547885 D2P_ALARM_DCDCTeSaplgErr 0 "No Alarm" 1 "Alarm Occur" ;
VAL_ 2149547885 D2P_ALARM_VoltSamplingErr 0 "No Alarm" 1 "Alarm Occur" ;
VAL_ 2149547885 D2P_ALARM_HgSdCuSaplgErr 0 "No Alarm" 1 "Alarm Occur" ;
VAL_ 2149547885 D2P_ALARM_CtrlCurrSamplingErr 0 "No Alarm" 1 "Alarm Occur" ;
VAL_ 2149547885 D2P_ALARM_BypassFail 0 "No Alarm" 1 "Alarm Occur" ;
VAL_ 2149547885 D2P_ALARM_Reserve1 0 "No Alarm" 1 "Alarm Occur" ;
VAL_ 2149547885 D2P_ALARM_Reserve2 0 "No Alarm" 1 "Alarm Occur" ;
VAL_ 2149547885 D2P_ALARM_Reserve3 0 "No Alarm" 1 "Alarm Occur" ;
VAL_ 2149547885 D2P_ALARM_Reserve4 0 "No Alarm" 1 "Alarm Occur" ;
VAL_ 2149547885 D2P_ALARM_Reserve5 0 "No Alarm" 1 "Alarm Occur" ;
VAL_ 2149547885 D2P_ALARM_Reserve6 0 "No Alarm" 1 "Alarm Occur" ;
VAL_ 2149547885 D2P_ALARM_Reserve7 0 "No Alarm" 1 "Alarm Occur" ;
VAL_ 2149547885 D2P_ALARM_Reserve8 0 "No Alarm" 1 "Alarm Occur" ;
VAL_ 2149547885 D2P_ALARM_Reserve9 0 "No Alarm" 1 "Alarm Occur" ;
VAL_ 2149547885 D2P_ALARM_Reserve10 0 "No Alarm" 1 "Alarm Occur" ;
VAL_ 2149547885 D2P_ALARM_Reserve11 0 "No Alarm" 1 "Alarm Occur" ;
VAL_ 2149547886 D2P_ALARM_EnvExtreOverTemp 0 "No Alarm" 1 "Alarm Occur" ;
VAL_ 2149547886 D2P_ALARM_EnvOverTemp 0 "No Alarm" 1 "Alarm Occur" ;
VAL_ 2149547886 D2P_ALARM_MosOverTemp 0 "No Alarm" 1 "Alarm Occur" ;
VAL_ 2149547886 D2P_ALARM_MosExtreOverTemp 0 "No Alarm" 1 "Alarm Occur" ;
VAL_ 2149547886 D2P_ALARM_HighSideOverVolt 0 "No Alarm" 1 "Alarm Occur" ;
VAL_ 2149547886 D2P_ALARM_HighSideUnderVolt 0 "No Alarm" 1 "Alarm Occur" ;
VAL_ 2149547886 D2P_ALARM_LowSideOverVolt 0 "No Alarm" 1 "Alarm Occur" ;
VAL_ 2149547886 D2P_ALARM_HighSideOverCurr 0 "No Alarm" 1 "Alarm Occur" ;
VAL_ 2149547886 D2P_ALARM_LowSideOverCurr_HW 0 "No Alarm" 1 "Alarm Occur" ;
VAL_ 2149547886 D2P_ALARM_LowSideOverCurr_SW 0 "No Alarm" 1 "Alarm Occur" ;
VAL_ 2149547886 D2P_ALARM_SecSideOverCurr_HW 0 "No Alarm" 1 "Alarm Occur" ;
VAL_ 2149547886 D2P_ALARM_SecSideOverCurr_SW 0 "No Alarm" 1 "Alarm Occur" ;
VAL_ 2149547886 D2P_ALARM_PriSideOverCurr_HW 0 "No Alarm" 1 "Alarm Occur" ;
VAL_ 2149547886 D2P_ALARM_PriSideOverCurr_SW 0 "No Alarm" 1 "Alarm Occur" ;
VAL_ 2149547886 D2P_ALARM_LowPowerSupplyErr 0 "No Alarm" 1 "Alarm Occur" ;
VAL_ 2149547886 D2P_ALARM_MBMUComErr 0 "No Alarm" 1 "Alarm Occur" ;
VAL_ 2149547886 D2P_ALARM_DCDCMsTeSaplgErr 0 "No Alarm" 1 "Alarm Occur" ;
VAL_ 2149547886 D2P_ALARM_DCDCTeSaplgErr 0 "No Alarm" 1 "Alarm Occur" ;
VAL_ 2149547886 D2P_ALARM_VoltSamplingErr 0 "No Alarm" 1 "Alarm Occur" ;
VAL_ 2149547886 D2P_ALARM_HgSdCuSaplgErr 0 "No Alarm" 1 "Alarm Occur" ;
VAL_ 2149547886 D2P_ALARM_CtrlCurrSamplingErr 0 "No Alarm" 1 "Alarm Occur" ;
VAL_ 2149547886 D2P_ALARM_BypassFail 0 "No Alarm" 1 "Alarm Occur" ;
VAL_ 2149547886 D2P_ALARM_Reserve1 0 "No Alarm" 1 "Alarm Occur" ;
VAL_ 2149547886 D2P_ALARM_Reserve2 0 "No Alarm" 1 "Alarm Occur" ;
VAL_ 2149547886 D2P_ALARM_Reserve3 0 "No Alarm" 1 "Alarm Occur" ;
VAL_ 2149547886 D2P_ALARM_Reserve4 0 "No Alarm" 1 "Alarm Occur" ;
VAL_ 2149547886 D2P_ALARM_Reserve5 0 "No Alarm" 1 "Alarm Occur" ;
VAL_ 2149547886 D2P_ALARM_Reserve6 0 "No Alarm" 1 "Alarm Occur" ;
VAL_ 2149547886 D2P_ALARM_Reserve7 0 "No Alarm" 1 "Alarm Occur" ;
VAL_ 2149547886 D2P_ALARM_Reserve8 0 "No Alarm" 1 "Alarm Occur" ;
VAL_ 2149547886 D2P_ALARM_Reserve9 0 "No Alarm" 1 "Alarm Occur" ;
VAL_ 2149547886 D2P_ALARM_Reserve10 0 "No Alarm" 1 "Alarm Occur" ;
VAL_ 2149547886 D2P_ALARM_Reserve11 0 "No Alarm" 1 "Alarm Occur" ;
VAL_ 2149547887 D2P_ALARM_EnvExtreOverTemp 0 "No Alarm" 1 "Alarm Occur" ;
VAL_ 2149547887 D2P_ALARM_EnvOverTemp 0 "No Alarm" 1 "Alarm Occur" ;
VAL_ 2149547887 D2P_ALARM_MosOverTemp 0 "No Alarm" 1 "Alarm Occur" ;
VAL_ 2149547887 D2P_ALARM_MosExtreOverTemp 0 "No Alarm" 1 "Alarm Occur" ;
VAL_ 2149547887 D2P_ALARM_HighSideOverVolt 0 "No Alarm" 1 "Alarm Occur" ;
VAL_ 2149547887 D2P_ALARM_HighSideUnderVolt 0 "No Alarm" 1 "Alarm Occur" ;
VAL_ 2149547887 D2P_ALARM_LowSideOverVolt 0 "No Alarm" 1 "Alarm Occur" ;
VAL_ 2149547887 D2P_ALARM_HighSideOverCurr 0 "No Alarm" 1 "Alarm Occur" ;
VAL_ 2149547887 D2P_ALARM_LowSideOverCurr_HW 0 "No Alarm" 1 "Alarm Occur" ;
VAL_ 2149547887 D2P_ALARM_LowSideOverCurr_SW 0 "No Alarm" 1 "Alarm Occur" ;
VAL_ 2149547887 D2P_ALARM_SecSideOverCurr_HW 0 "No Alarm" 1 "Alarm Occur" ;
VAL_ 2149547887 D2P_ALARM_SecSideOverCurr_SW 0 "No Alarm" 1 "Alarm Occur" ;
VAL_ 2149547887 D2P_ALARM_PriSideOverCurr_HW 0 "No Alarm" 1 "Alarm Occur" ;
VAL_ 2149547887 D2P_ALARM_PriSideOverCurr_SW 0 "No Alarm" 1 "Alarm Occur" ;
VAL_ 2149547887 D2P_ALARM_LowPowerSupplyErr 0 "No Alarm" 1 "Alarm Occur" ;
VAL_ 2149547887 D2P_ALARM_MBMUComErr 0 "No Alarm" 1 "Alarm Occur" ;
VAL_ 2149547887 D2P_ALARM_DCDCMsTeSaplgErr 0 "No Alarm" 1 "Alarm Occur" ;
VAL_ 2149547887 D2P_ALARM_DCDCTeSaplgErr 0 "No Alarm" 1 "Alarm Occur" ;
VAL_ 2149547887 D2P_ALARM_VoltSamplingErr 0 "No Alarm" 1 "Alarm Occur" ;
VAL_ 2149547887 D2P_ALARM_HgSdCuSaplgErr 0 "No Alarm" 1 "Alarm Occur" ;
VAL_ 2149547887 D2P_ALARM_CtrlCurrSamplingErr 0 "No Alarm" 1 "Alarm Occur" ;
VAL_ 2149547887 D2P_ALARM_BypassFail 0 "No Alarm" 1 "Alarm Occur" ;
VAL_ 2149547887 D2P_ALARM_Reserve1 0 "No Alarm" 1 "Alarm Occur" ;
VAL_ 2149547887 D2P_ALARM_Reserve2 0 "No Alarm" 1 "Alarm Occur" ;
VAL_ 2149547887 D2P_ALARM_Reserve3 0 "No Alarm" 1 "Alarm Occur" ;
VAL_ 2149547887 D2P_ALARM_Reserve4 0 "No Alarm" 1 "Alarm Occur" ;
VAL_ 2149547887 D2P_ALARM_Reserve5 0 "No Alarm" 1 "Alarm Occur" ;
VAL_ 2149547887 D2P_ALARM_Reserve6 0 "No Alarm" 1 "Alarm Occur" ;
VAL_ 2149547887 D2P_ALARM_Reserve7 0 "No Alarm" 1 "Alarm Occur" ;
VAL_ 2149547887 D2P_ALARM_Reserve8 0 "No Alarm" 1 "Alarm Occur" ;
VAL_ 2149547887 D2P_ALARM_Reserve9 0 "No Alarm" 1 "Alarm Occur" ;
VAL_ 2149547887 D2P_ALARM_Reserve10 0 "No Alarm" 1 "Alarm Occur" ;
VAL_ 2149547887 D2P_ALARM_Reserve11 0 "No Alarm" 1 "Alarm Occur" ;
VAL_ 2149547888 D2P_ALARM_EnvExtreOverTemp 0 "No Alarm" 1 "Alarm Occur" ;
VAL_ 2149547888 D2P_ALARM_EnvOverTemp 0 "No Alarm" 1 "Alarm Occur" ;
VAL_ 2149547888 D2P_ALARM_MosOverTemp 0 "No Alarm" 1 "Alarm Occur" ;
VAL_ 2149547888 D2P_ALARM_MosExtreOverTemp 0 "No Alarm" 1 "Alarm Occur" ;
VAL_ 2149547888 D2P_ALARM_HighSideOverVolt 0 "No Alarm" 1 "Alarm Occur" ;
VAL_ 2149547888 D2P_ALARM_HighSideUnderVolt 0 "No Alarm" 1 "Alarm Occur" ;
VAL_ 2149547888 D2P_ALARM_LowSideOverVolt 0 "No Alarm" 1 "Alarm Occur" ;
VAL_ 2149547888 D2P_ALARM_HighSideOverCurr 0 "No Alarm" 1 "Alarm Occur" ;
VAL_ 2149547888 D2P_ALARM_LowSideOverCurr_HW 0 "No Alarm" 1 "Alarm Occur" ;
VAL_ 2149547888 D2P_ALARM_LowSideOverCurr_SW 0 "No Alarm" 1 "Alarm Occur" ;
VAL_ 2149547888 D2P_ALARM_SecSideOverCurr_HW 0 "No Alarm" 1 "Alarm Occur" ;
VAL_ 2149547888 D2P_ALARM_SecSideOverCurr_SW 0 "No Alarm" 1 "Alarm Occur" ;
VAL_ 2149547888 D2P_ALARM_PriSideOverCurr_HW 0 "No Alarm" 1 "Alarm Occur" ;
VAL_ 2149547888 D2P_ALARM_PriSideOverCurr_SW 0 "No Alarm" 1 "Alarm Occur" ;
VAL_ 2149547888 D2P_ALARM_LowPowerSupplyErr 0 "No Alarm" 1 "Alarm Occur" ;
VAL_ 2149547888 D2P_ALARM_MBMUComErr 0 "No Alarm" 1 "Alarm Occur" ;
VAL_ 2149547888 D2P_ALARM_DCDCMsTeSaplgErr 0 "No Alarm" 1 "Alarm Occur" ;
VAL_ 2149547888 D2P_ALARM_DCDCTeSaplgErr 0 "No Alarm" 1 "Alarm Occur" ;
VAL_ 2149547888 D2P_ALARM_VoltSamplingErr 0 "No Alarm" 1 "Alarm Occur" ;
VAL_ 2149547888 D2P_ALARM_HgSdCuSaplgErr 0 "No Alarm" 1 "Alarm Occur" ;
VAL_ 2149547888 D2P_ALARM_CtrlCurrSamplingErr 0 "No Alarm" 1 "Alarm Occur" ;
VAL_ 2149547888 D2P_ALARM_BypassFail 0 "No Alarm" 1 "Alarm Occur" ;
VAL_ 2149547888 D2P_ALARM_Reserve1 0 "No Alarm" 1 "Alarm Occur" ;
VAL_ 2149547888 D2P_ALARM_Reserve2 0 "No Alarm" 1 "Alarm Occur" ;
VAL_ 2149547888 D2P_ALARM_Reserve3 0 "No Alarm" 1 "Alarm Occur" ;
VAL_ 2149547888 D2P_ALARM_Reserve4 0 "No Alarm" 1 "Alarm Occur" ;
VAL_ 2149547888 D2P_ALARM_Reserve5 0 "No Alarm" 1 "Alarm Occur" ;
VAL_ 2149547888 D2P_ALARM_Reserve6 0 "No Alarm" 1 "Alarm Occur" ;
VAL_ 2149547888 D2P_ALARM_Reserve7 0 "No Alarm" 1 "Alarm Occur" ;
VAL_ 2149547888 D2P_ALARM_Reserve8 0 "No Alarm" 1 "Alarm Occur" ;
VAL_ 2149547888 D2P_ALARM_Reserve9 0 "No Alarm" 1 "Alarm Occur" ;
VAL_ 2149547888 D2P_ALARM_Reserve10 0 "No Alarm" 1 "Alarm Occur" ;
VAL_ 2149547888 D2P_ALARM_Reserve11 0 "No Alarm" 1 "Alarm Occur" ;
VAL_ 2149547889 D2P_ALARM_EnvExtreOverTemp 0 "No Alarm" 1 "Alarm Occur" ;
VAL_ 2149547889 D2P_ALARM_EnvOverTemp 0 "No Alarm" 1 "Alarm Occur" ;
VAL_ 2149547889 D2P_ALARM_MosOverTemp 0 "No Alarm" 1 "Alarm Occur" ;
VAL_ 2149547889 D2P_ALARM_MosExtreOverTemp 0 "No Alarm" 1 "Alarm Occur" ;
VAL_ 2149547889 D2P_ALARM_HighSideOverVolt 0 "No Alarm" 1 "Alarm Occur" ;
VAL_ 2149547889 D2P_ALARM_HighSideUnderVolt 0 "No Alarm" 1 "Alarm Occur" ;
VAL_ 2149547889 D2P_ALARM_LowSideOverVolt 0 "No Alarm" 1 "Alarm Occur" ;
VAL_ 2149547889 D2P_ALARM_HighSideOverCurr 0 "No Alarm" 1 "Alarm Occur" ;
VAL_ 2149547889 D2P_ALARM_LowSideOverCurr_HW 0 "No Alarm" 1 "Alarm Occur" ;
VAL_ 2149547889 D2P_ALARM_LowSideOverCurr_SW 0 "No Alarm" 1 "Alarm Occur" ;
VAL_ 2149547889 D2P_ALARM_SecSideOverCurr_HW 0 "No Alarm" 1 "Alarm Occur" ;
VAL_ 2149547889 D2P_ALARM_SecSideOverCurr_SW 0 "No Alarm" 1 "Alarm Occur" ;
VAL_ 2149547889 D2P_ALARM_PriSideOverCurr_HW 0 "No Alarm" 1 "Alarm Occur" ;
VAL_ 2149547889 D2P_ALARM_PriSideOverCurr_SW 0 "No Alarm" 1 "Alarm Occur" ;
VAL_ 2149547889 D2P_ALARM_LowPowerSupplyErr 0 "No Alarm" 1 "Alarm Occur" ;
VAL_ 2149547889 D2P_ALARM_MBMUComErr 0 "No Alarm" 1 "Alarm Occur" ;
VAL_ 2149547889 D2P_ALARM_DCDCMsTeSaplgErr 0 "No Alarm" 1 "Alarm Occur" ;
VAL_ 2149547889 D2P_ALARM_DCDCTeSaplgErr 0 "No Alarm" 1 "Alarm Occur" ;
VAL_ 2149547889 D2P_ALARM_VoltSamplingErr 0 "No Alarm" 1 "Alarm Occur" ;
VAL_ 2149547889 D2P_ALARM_HgSdCuSaplgErr 0 "No Alarm" 1 "Alarm Occur" ;
VAL_ 2149547889 D2P_ALARM_CtrlCurrSamplingErr 0 "No Alarm" 1 "Alarm Occur" ;
VAL_ 2149547889 D2P_ALARM_BypassFail 0 "No Alarm" 1 "Alarm Occur" ;
VAL_ 2149547889 D2P_ALARM_Reserve1 0 "No Alarm" 1 "Alarm Occur" ;
VAL_ 2149547889 D2P_ALARM_Reserve2 0 "No Alarm" 1 "Alarm Occur" ;
VAL_ 2149547889 D2P_ALARM_Reserve3 0 "No Alarm" 1 "Alarm Occur" ;
VAL_ 2149547889 D2P_ALARM_Reserve4 0 "No Alarm" 1 "Alarm Occur" ;
VAL_ 2149547889 D2P_ALARM_Reserve5 0 "No Alarm" 1 "Alarm Occur" ;
VAL_ 2149547889 D2P_ALARM_Reserve6 0 "No Alarm" 1 "Alarm Occur" ;
VAL_ 2149547889 D2P_ALARM_Reserve7 0 "No Alarm" 1 "Alarm Occur" ;
VAL_ 2149547889 D2P_ALARM_Reserve8 0 "No Alarm" 1 "Alarm Occur" ;
VAL_ 2149547889 D2P_ALARM_Reserve9 0 "No Alarm" 1 "Alarm Occur" ;
VAL_ 2149547889 D2P_ALARM_Reserve10 0 "No Alarm" 1 "Alarm Occur" ;
VAL_ 2149547889 D2P_ALARM_Reserve11 0 "No Alarm" 1 "Alarm Occur" ;
VAL_ 2149547890 D2P_ALARM_EnvExtreOverTemp 0 "No Alarm" 1 "Alarm Occur" ;
VAL_ 2149547890 D2P_ALARM_EnvOverTemp 0 "No Alarm" 1 "Alarm Occur" ;
VAL_ 2149547890 D2P_ALARM_MosOverTemp 0 "No Alarm" 1 "Alarm Occur" ;
VAL_ 2149547890 D2P_ALARM_MosExtreOverTemp 0 "No Alarm" 1 "Alarm Occur" ;
VAL_ 2149547890 D2P_ALARM_HighSideOverVolt 0 "No Alarm" 1 "Alarm Occur" ;
VAL_ 2149547890 D2P_ALARM_HighSideUnderVolt 0 "No Alarm" 1 "Alarm Occur" ;
VAL_ 2149547890 D2P_ALARM_LowSideOverVolt 0 "No Alarm" 1 "Alarm Occur" ;
VAL_ 2149547890 D2P_ALARM_HighSideOverCurr 0 "No Alarm" 1 "Alarm Occur" ;
VAL_ 2149547890 D2P_ALARM_LowSideOverCurr_HW 0 "No Alarm" 1 "Alarm Occur" ;
VAL_ 2149547890 D2P_ALARM_LowSideOverCurr_SW 0 "No Alarm" 1 "Alarm Occur" ;
VAL_ 2149547890 D2P_ALARM_SecSideOverCurr_HW 0 "No Alarm" 1 "Alarm Occur" ;
VAL_ 2149547890 D2P_ALARM_SecSideOverCurr_SW 0 "No Alarm" 1 "Alarm Occur" ;
VAL_ 2149547890 D2P_ALARM_PriSideOverCurr_HW 0 "No Alarm" 1 "Alarm Occur" ;
VAL_ 2149547890 D2P_ALARM_PriSideOverCurr_SW 0 "No Alarm" 1 "Alarm Occur" ;
VAL_ 2149547890 D2P_ALARM_LowPowerSupplyErr 0 "No Alarm" 1 "Alarm Occur" ;
VAL_ 2149547890 D2P_ALARM_MBMUComErr 0 "No Alarm" 1 "Alarm Occur" ;
VAL_ 2149547890 D2P_ALARM_DCDCMsTeSaplgErr 0 "No Alarm" 1 "Alarm Occur" ;
VAL_ 2149547890 D2P_ALARM_DCDCTeSaplgErr 0 "No Alarm" 1 "Alarm Occur" ;
VAL_ 2149547890 D2P_ALARM_VoltSamplingErr 0 "No Alarm" 1 "Alarm Occur" ;
VAL_ 2149547890 D2P_ALARM_HgSdCuSaplgErr 0 "No Alarm" 1 "Alarm Occur" ;
VAL_ 2149547890 D2P_ALARM_CtrlCurrSamplingErr 0 "No Alarm" 1 "Alarm Occur" ;
VAL_ 2149547890 D2P_ALARM_BypassFail 0 "No Alarm" 1 "Alarm Occur" ;
VAL_ 2149547890 D2P_ALARM_Reserve1 0 "No Alarm" 1 "Alarm Occur" ;
VAL_ 2149547890 D2P_ALARM_Reserve2 0 "No Alarm" 1 "Alarm Occur" ;
VAL_ 2149547890 D2P_ALARM_Reserve3 0 "No Alarm" 1 "Alarm Occur" ;
VAL_ 2149547890 D2P_ALARM_Reserve4 0 "No Alarm" 1 "Alarm Occur" ;
VAL_ 2149547890 D2P_ALARM_Reserve5 0 "No Alarm" 1 "Alarm Occur" ;
VAL_ 2149547890 D2P_ALARM_Reserve6 0 "No Alarm" 1 "Alarm Occur" ;
VAL_ 2149547890 D2P_ALARM_Reserve7 0 "No Alarm" 1 "Alarm Occur" ;
VAL_ 2149547890 D2P_ALARM_Reserve8 0 "No Alarm" 1 "Alarm Occur" ;
VAL_ 2149547890 D2P_ALARM_Reserve9 0 "No Alarm" 1 "Alarm Occur" ;
VAL_ 2149547890 D2P_ALARM_Reserve10 0 "No Alarm" 1 "Alarm Occur" ;
VAL_ 2149547890 D2P_ALARM_Reserve11 0 "No Alarm" 1 "Alarm Occur" ;
VAL_ 2149547891 D2P_ALARM_EnvExtreOverTemp 0 "No Alarm" 1 "Alarm Occur" ;
VAL_ 2149547891 D2P_ALARM_EnvOverTemp 0 "No Alarm" 1 "Alarm Occur" ;
VAL_ 2149547891 D2P_ALARM_MosOverTemp 0 "No Alarm" 1 "Alarm Occur" ;
VAL_ 2149547891 D2P_ALARM_MosExtreOverTemp 0 "No Alarm" 1 "Alarm Occur" ;
VAL_ 2149547891 D2P_ALARM_HighSideOverVolt 0 "No Alarm" 1 "Alarm Occur" ;
VAL_ 2149547891 D2P_ALARM_HighSideUnderVolt 0 "No Alarm" 1 "Alarm Occur" ;
VAL_ 2149547891 D2P_ALARM_LowSideOverVolt 0 "No Alarm" 1 "Alarm Occur" ;
VAL_ 2149547891 D2P_ALARM_HighSideOverCurr 0 "No Alarm" 1 "Alarm Occur" ;
VAL_ 2149547891 D2P_ALARM_LowSideOverCurr_HW 0 "No Alarm" 1 "Alarm Occur" ;
VAL_ 2149547891 D2P_ALARM_LowSideOverCurr_SW 0 "No Alarm" 1 "Alarm Occur" ;
VAL_ 2149547891 D2P_ALARM_SecSideOverCurr_HW 0 "No Alarm" 1 "Alarm Occur" ;
VAL_ 2149547891 D2P_ALARM_SecSideOverCurr_SW 0 "No Alarm" 1 "Alarm Occur" ;
VAL_ 2149547891 D2P_ALARM_PriSideOverCurr_HW 0 "No Alarm" 1 "Alarm Occur" ;
VAL_ 2149547891 D2P_ALARM_PriSideOverCurr_SW 0 "No Alarm" 1 "Alarm Occur" ;
VAL_ 2149547891 D2P_ALARM_LowPowerSupplyErr 0 "No Alarm" 1 "Alarm Occur" ;
VAL_ 2149547891 D2P_ALARM_MBMUComErr 0 "No Alarm" 1 "Alarm Occur" ;
VAL_ 2149547891 D2P_ALARM_DCDCMsTeSaplgErr 0 "No Alarm" 1 "Alarm Occur" ;
VAL_ 2149547891 D2P_ALARM_DCDCTeSaplgErr 0 "No Alarm" 1 "Alarm Occur" ;
VAL_ 2149547891 D2P_ALARM_VoltSamplingErr 0 "No Alarm" 1 "Alarm Occur" ;
VAL_ 2149547891 D2P_ALARM_HgSdCuSaplgErr 0 "No Alarm" 1 "Alarm Occur" ;
VAL_ 2149547891 D2P_ALARM_CtrlCurrSamplingErr 0 "No Alarm" 1 "Alarm Occur" ;
VAL_ 2149547891 D2P_ALARM_BypassFail 0 "No Alarm" 1 "Alarm Occur" ;
VAL_ 2149547891 D2P_ALARM_Reserve1 0 "No Alarm" 1 "Alarm Occur" ;
VAL_ 2149547891 D2P_ALARM_Reserve2 0 "No Alarm" 1 "Alarm Occur" ;
VAL_ 2149547891 D2P_ALARM_Reserve3 0 "No Alarm" 1 "Alarm Occur" ;
VAL_ 2149547891 D2P_ALARM_Reserve4 0 "No Alarm" 1 "Alarm Occur" ;
VAL_ 2149547891 D2P_ALARM_Reserve5 0 "No Alarm" 1 "Alarm Occur" ;
VAL_ 2149547891 D2P_ALARM_Reserve6 0 "No Alarm" 1 "Alarm Occur" ;
VAL_ 2149547891 D2P_ALARM_Reserve7 0 "No Alarm" 1 "Alarm Occur" ;
VAL_ 2149547891 D2P_ALARM_Reserve8 0 "No Alarm" 1 "Alarm Occur" ;
VAL_ 2149547891 D2P_ALARM_Reserve9 0 "No Alarm" 1 "Alarm Occur" ;
VAL_ 2149547891 D2P_ALARM_Reserve10 0 "No Alarm" 1 "Alarm Occur" ;
VAL_ 2149547891 D2P_ALARM_Reserve11 0 "No Alarm" 1 "Alarm Occur" ;
VAL_ 2149547892 D2P_ALARM_EnvExtreOverTemp 0 "No Alarm" 1 "Alarm Occur" ;
VAL_ 2149547892 D2P_ALARM_EnvOverTemp 0 "No Alarm" 1 "Alarm Occur" ;
VAL_ 2149547892 D2P_ALARM_MosOverTemp 0 "No Alarm" 1 "Alarm Occur" ;
VAL_ 2149547892 D2P_ALARM_MosExtreOverTemp 0 "No Alarm" 1 "Alarm Occur" ;
VAL_ 2149547892 D2P_ALARM_HighSideOverVolt 0 "No Alarm" 1 "Alarm Occur" ;
VAL_ 2149547892 D2P_ALARM_HighSideUnderVolt 0 "No Alarm" 1 "Alarm Occur" ;
VAL_ 2149547892 D2P_ALARM_LowSideOverVolt 0 "No Alarm" 1 "Alarm Occur" ;
VAL_ 2149547892 D2P_ALARM_HighSideOverCurr 0 "No Alarm" 1 "Alarm Occur" ;
VAL_ 2149547892 D2P_ALARM_LowSideOverCurr_HW 0 "No Alarm" 1 "Alarm Occur" ;
VAL_ 2149547892 D2P_ALARM_LowSideOverCurr_SW 0 "No Alarm" 1 "Alarm Occur" ;
VAL_ 2149547892 D2P_ALARM_SecSideOverCurr_HW 0 "No Alarm" 1 "Alarm Occur" ;
VAL_ 2149547892 D2P_ALARM_SecSideOverCurr_SW 0 "No Alarm" 1 "Alarm Occur" ;
VAL_ 2149547892 D2P_ALARM_PriSideOverCurr_HW 0 "No Alarm" 1 "Alarm Occur" ;
VAL_ 2149547892 D2P_ALARM_PriSideOverCurr_SW 0 "No Alarm" 1 "Alarm Occur" ;
VAL_ 2149547892 D2P_ALARM_LowPowerSupplyErr 0 "No Alarm" 1 "Alarm Occur" ;
VAL_ 2149547892 D2P_ALARM_MBMUComErr 0 "No Alarm" 1 "Alarm Occur" ;
VAL_ 2149547892 D2P_ALARM_DCDCMsTeSaplgErr 0 "No Alarm" 1 "Alarm Occur" ;
VAL_ 2149547892 D2P_ALARM_DCDCTeSaplgErr 0 "No Alarm" 1 "Alarm Occur" ;
VAL_ 2149547892 D2P_ALARM_VoltSamplingErr 0 "No Alarm" 1 "Alarm Occur" ;
VAL_ 2149547892 D2P_ALARM_HgSdCuSaplgErr 0 "No Alarm" 1 "Alarm Occur" ;
VAL_ 2149547892 D2P_ALARM_CtrlCurrSamplingErr 0 "No Alarm" 1 "Alarm Occur" ;
VAL_ 2149547892 D2P_ALARM_BypassFail 0 "No Alarm" 1 "Alarm Occur" ;
VAL_ 2149547892 D2P_ALARM_Reserve1 0 "No Alarm" 1 "Alarm Occur" ;
VAL_ 2149547892 D2P_ALARM_Reserve2 0 "No Alarm" 1 "Alarm Occur" ;
VAL_ 2149547892 D2P_ALARM_Reserve3 0 "No Alarm" 1 "Alarm Occur" ;
VAL_ 2149547892 D2P_ALARM_Reserve4 0 "No Alarm" 1 "Alarm Occur" ;
VAL_ 2149547892 D2P_ALARM_Reserve5 0 "No Alarm" 1 "Alarm Occur" ;
VAL_ 2149547892 D2P_ALARM_Reserve6 0 "No Alarm" 1 "Alarm Occur" ;
VAL_ 2149547892 D2P_ALARM_Reserve7 0 "No Alarm" 1 "Alarm Occur" ;
VAL_ 2149547892 D2P_ALARM_Reserve8 0 "No Alarm" 1 "Alarm Occur" ;
VAL_ 2149547892 D2P_ALARM_Reserve9 0 "No Alarm" 1 "Alarm Occur" ;
VAL_ 2149547892 D2P_ALARM_Reserve10 0 "No Alarm" 1 "Alarm Occur" ;
VAL_ 2149547892 D2P_ALARM_Reserve11 0 "No Alarm" 1 "Alarm Occur" ;
VAL_ 2149547893 D2P_ALARM_EnvExtreOverTemp 0 "No Alarm" 1 "Alarm Occur" ;
VAL_ 2149547893 D2P_ALARM_EnvOverTemp 0 "No Alarm" 1 "Alarm Occur" ;
VAL_ 2149547893 D2P_ALARM_MosOverTemp 0 "No Alarm" 1 "Alarm Occur" ;
VAL_ 2149547893 D2P_ALARM_MosExtreOverTemp 0 "No Alarm" 1 "Alarm Occur" ;
VAL_ 2149547893 D2P_ALARM_HighSideOverVolt 0 "No Alarm" 1 "Alarm Occur" ;
VAL_ 2149547893 D2P_ALARM_HighSideUnderVolt 0 "No Alarm" 1 "Alarm Occur" ;
VAL_ 2149547893 D2P_ALARM_LowSideOverVolt 0 "No Alarm" 1 "Alarm Occur" ;
VAL_ 2149547893 D2P_ALARM_HighSideOverCurr 0 "No Alarm" 1 "Alarm Occur" ;
VAL_ 2149547893 D2P_ALARM_LowSideOverCurr_HW 0 "No Alarm" 1 "Alarm Occur" ;
VAL_ 2149547893 D2P_ALARM_LowSideOverCurr_SW 0 "No Alarm" 1 "Alarm Occur" ;
VAL_ 2149547893 D2P_ALARM_SecSideOverCurr_HW 0 "No Alarm" 1 "Alarm Occur" ;
VAL_ 2149547893 D2P_ALARM_SecSideOverCurr_SW 0 "No Alarm" 1 "Alarm Occur" ;
VAL_ 2149547893 D2P_ALARM_PriSideOverCurr_HW 0 "No Alarm" 1 "Alarm Occur" ;
VAL_ 2149547893 D2P_ALARM_PriSideOverCurr_SW 0 "No Alarm" 1 "Alarm Occur" ;
VAL_ 2149547893 D2P_ALARM_LowPowerSupplyErr 0 "No Alarm" 1 "Alarm Occur" ;
VAL_ 2149547893 D2P_ALARM_MBMUComErr 0 "No Alarm" 1 "Alarm Occur" ;
VAL_ 2149547893 D2P_ALARM_DCDCMsTeSaplgErr 0 "No Alarm" 1 "Alarm Occur" ;
VAL_ 2149547893 D2P_ALARM_DCDCTeSaplgErr 0 "No Alarm" 1 "Alarm Occur" ;
VAL_ 2149547893 D2P_ALARM_VoltSamplingErr 0 "No Alarm" 1 "Alarm Occur" ;
VAL_ 2149547893 D2P_ALARM_HgSdCuSaplgErr 0 "No Alarm" 1 "Alarm Occur" ;
VAL_ 2149547893 D2P_ALARM_CtrlCurrSamplingErr 0 "No Alarm" 1 "Alarm Occur" ;
VAL_ 2149547893 D2P_ALARM_BypassFail 0 "No Alarm" 1 "Alarm Occur" ;
VAL_ 2149547893 D2P_ALARM_Reserve1 0 "No Alarm" 1 "Alarm Occur" ;
VAL_ 2149547893 D2P_ALARM_Reserve2 0 "No Alarm" 1 "Alarm Occur" ;
VAL_ 2149547893 D2P_ALARM_Reserve3 0 "No Alarm" 1 "Alarm Occur" ;
VAL_ 2149547893 D2P_ALARM_Reserve4 0 "No Alarm" 1 "Alarm Occur" ;
VAL_ 2149547893 D2P_ALARM_Reserve5 0 "No Alarm" 1 "Alarm Occur" ;
VAL_ 2149547893 D2P_ALARM_Reserve6 0 "No Alarm" 1 "Alarm Occur" ;
VAL_ 2149547893 D2P_ALARM_Reserve7 0 "No Alarm" 1 "Alarm Occur" ;
VAL_ 2149547893 D2P_ALARM_Reserve8 0 "No Alarm" 1 "Alarm Occur" ;
VAL_ 2149547893 D2P_ALARM_Reserve9 0 "No Alarm" 1 "Alarm Occur" ;
VAL_ 2149547893 D2P_ALARM_Reserve10 0 "No Alarm" 1 "Alarm Occur" ;
VAL_ 2149547893 D2P_ALARM_Reserve11 0 "No Alarm" 1 "Alarm Occur" ;
VAL_ 2149547894 D2P_ALARM_EnvExtreOverTemp 0 "No Alarm" 1 "Alarm Occur" ;
VAL_ 2149547894 D2P_ALARM_EnvOverTemp 0 "No Alarm" 1 "Alarm Occur" ;
VAL_ 2149547894 D2P_ALARM_MosOverTemp 0 "No Alarm" 1 "Alarm Occur" ;
VAL_ 2149547894 D2P_ALARM_MosExtreOverTemp 0 "No Alarm" 1 "Alarm Occur" ;
VAL_ 2149547894 D2P_ALARM_HighSideOverVolt 0 "No Alarm" 1 "Alarm Occur" ;
VAL_ 2149547894 D2P_ALARM_HighSideUnderVolt 0 "No Alarm" 1 "Alarm Occur" ;
VAL_ 2149547894 D2P_ALARM_LowSideOverVolt 0 "No Alarm" 1 "Alarm Occur" ;
VAL_ 2149547894 D2P_ALARM_HighSideOverCurr 0 "No Alarm" 1 "Alarm Occur" ;
VAL_ 2149547894 D2P_ALARM_LowSideOverCurr_HW 0 "No Alarm" 1 "Alarm Occur" ;
VAL_ 2149547894 D2P_ALARM_LowSideOverCurr_SW 0 "No Alarm" 1 "Alarm Occur" ;
VAL_ 2149547894 D2P_ALARM_SecSideOverCurr_HW 0 "No Alarm" 1 "Alarm Occur" ;
VAL_ 2149547894 D2P_ALARM_SecSideOverCurr_SW 0 "No Alarm" 1 "Alarm Occur" ;
VAL_ 2149547894 D2P_ALARM_PriSideOverCurr_HW 0 "No Alarm" 1 "Alarm Occur" ;
VAL_ 2149547894 D2P_ALARM_PriSideOverCurr_SW 0 "No Alarm" 1 "Alarm Occur" ;
VAL_ 2149547894 D2P_ALARM_LowPowerSupplyErr 0 "No Alarm" 1 "Alarm Occur" ;
VAL_ 2149547894 D2P_ALARM_MBMUComErr 0 "No Alarm" 1 "Alarm Occur" ;
VAL_ 2149547894 D2P_ALARM_DCDCMsTeSaplgErr 0 "No Alarm" 1 "Alarm Occur" ;
VAL_ 2149547894 D2P_ALARM_DCDCTeSaplgErr 0 "No Alarm" 1 "Alarm Occur" ;
VAL_ 2149547894 D2P_ALARM_VoltSamplingErr 0 "No Alarm" 1 "Alarm Occur" ;
VAL_ 2149547894 D2P_ALARM_HgSdCuSaplgErr 0 "No Alarm" 1 "Alarm Occur" ;
VAL_ 2149547894 D2P_ALARM_CtrlCurrSamplingErr 0 "No Alarm" 1 "Alarm Occur" ;
VAL_ 2149547894 D2P_ALARM_BypassFail 0 "No Alarm" 1 "Alarm Occur" ;
VAL_ 2149547894 D2P_ALARM_Reserve1 0 "No Alarm" 1 "Alarm Occur" ;
VAL_ 2149547894 D2P_ALARM_Reserve2 0 "No Alarm" 1 "Alarm Occur" ;
VAL_ 2149547894 D2P_ALARM_Reserve3 0 "No Alarm" 1 "Alarm Occur" ;
VAL_ 2149547894 D2P_ALARM_Reserve4 0 "No Alarm" 1 "Alarm Occur" ;
VAL_ 2149547894 D2P_ALARM_Reserve5 0 "No Alarm" 1 "Alarm Occur" ;
VAL_ 2149547894 D2P_ALARM_Reserve6 0 "No Alarm" 1 "Alarm Occur" ;
VAL_ 2149547894 D2P_ALARM_Reserve7 0 "No Alarm" 1 "Alarm Occur" ;
VAL_ 2149547894 D2P_ALARM_Reserve8 0 "No Alarm" 1 "Alarm Occur" ;
VAL_ 2149547894 D2P_ALARM_Reserve9 0 "No Alarm" 1 "Alarm Occur" ;
VAL_ 2149547894 D2P_ALARM_Reserve10 0 "No Alarm" 1 "Alarm Occur" ;
VAL_ 2149547894 D2P_ALARM_Reserve11 0 "No Alarm" 1 "Alarm Occur" ;
VAL_ 2149547895 D2P_ALARM_EnvExtreOverTemp 0 "No Alarm" 1 "Alarm Occur" ;
VAL_ 2149547895 D2P_ALARM_EnvOverTemp 0 "No Alarm" 1 "Alarm Occur" ;
VAL_ 2149547895 D2P_ALARM_MosOverTemp 0 "No Alarm" 1 "Alarm Occur" ;
VAL_ 2149547895 D2P_ALARM_MosExtreOverTemp 0 "No Alarm" 1 "Alarm Occur" ;
VAL_ 2149547895 D2P_ALARM_HighSideOverVolt 0 "No Alarm" 1 "Alarm Occur" ;
VAL_ 2149547895 D2P_ALARM_HighSideUnderVolt 0 "No Alarm" 1 "Alarm Occur" ;
VAL_ 2149547895 D2P_ALARM_LowSideOverVolt 0 "No Alarm" 1 "Alarm Occur" ;
VAL_ 2149547895 D2P_ALARM_HighSideOverCurr 0 "No Alarm" 1 "Alarm Occur" ;
VAL_ 2149547895 D2P_ALARM_LowSideOverCurr_HW 0 "No Alarm" 1 "Alarm Occur" ;
VAL_ 2149547895 D2P_ALARM_LowSideOverCurr_SW 0 "No Alarm" 1 "Alarm Occur" ;
VAL_ 2149547895 D2P_ALARM_SecSideOverCurr_HW 0 "No Alarm" 1 "Alarm Occur" ;
VAL_ 2149547895 D2P_ALARM_SecSideOverCurr_SW 0 "No Alarm" 1 "Alarm Occur" ;
VAL_ 2149547895 D2P_ALARM_PriSideOverCurr_HW 0 "No Alarm" 1 "Alarm Occur" ;
VAL_ 2149547895 D2P_ALARM_PriSideOverCurr_SW 0 "No Alarm" 1 "Alarm Occur" ;
VAL_ 2149547895 D2P_ALARM_LowPowerSupplyErr 0 "No Alarm" 1 "Alarm Occur" ;
VAL_ 2149547895 D2P_ALARM_MBMUComErr 0 "No Alarm" 1 "Alarm Occur" ;
VAL_ 2149547895 D2P_ALARM_DCDCMsTeSaplgErr 0 "No Alarm" 1 "Alarm Occur" ;
VAL_ 2149547895 D2P_ALARM_DCDCTeSaplgErr 0 "No Alarm" 1 "Alarm Occur" ;
VAL_ 2149547895 D2P_ALARM_VoltSamplingErr 0 "No Alarm" 1 "Alarm Occur" ;
VAL_ 2149547895 D2P_ALARM_HgSdCuSaplgErr 0 "No Alarm" 1 "Alarm Occur" ;
VAL_ 2149547895 D2P_ALARM_CtrlCurrSamplingErr 0 "No Alarm" 1 "Alarm Occur" ;
VAL_ 2149547895 D2P_ALARM_BypassFail 0 "No Alarm" 1 "Alarm Occur" ;
VAL_ 2149547895 D2P_ALARM_Reserve1 0 "No Alarm" 1 "Alarm Occur" ;
VAL_ 2149547895 D2P_ALARM_Reserve2 0 "No Alarm" 1 "Alarm Occur" ;
VAL_ 2149547895 D2P_ALARM_Reserve3 0 "No Alarm" 1 "Alarm Occur" ;
VAL_ 2149547895 D2P_ALARM_Reserve4 0 "No Alarm" 1 "Alarm Occur" ;
VAL_ 2149547895 D2P_ALARM_Reserve5 0 "No Alarm" 1 "Alarm Occur" ;
VAL_ 2149547895 D2P_ALARM_Reserve6 0 "No Alarm" 1 "Alarm Occur" ;
VAL_ 2149547895 D2P_ALARM_Reserve7 0 "No Alarm" 1 "Alarm Occur" ;
VAL_ 2149547895 D2P_ALARM_Reserve8 0 "No Alarm" 1 "Alarm Occur" ;
VAL_ 2149547895 D2P_ALARM_Reserve9 0 "No Alarm" 1 "Alarm Occur" ;
VAL_ 2149547895 D2P_ALARM_Reserve10 0 "No Alarm" 1 "Alarm Occur" ;
VAL_ 2149547895 D2P_ALARM_Reserve11 0 "No Alarm" 1 "Alarm Occur" ;
VAL_ 2149547896 D2P_ALARM_EnvExtreOverTemp 0 "No Alarm" 1 "Alarm Occur" ;
VAL_ 2149547896 D2P_ALARM_EnvOverTemp 0 "No Alarm" 1 "Alarm Occur" ;
VAL_ 2149547896 D2P_ALARM_MosOverTemp 0 "No Alarm" 1 "Alarm Occur" ;
VAL_ 2149547896 D2P_ALARM_MosExtreOverTemp 0 "No Alarm" 1 "Alarm Occur" ;
VAL_ 2149547896 D2P_ALARM_HighSideOverVolt 0 "No Alarm" 1 "Alarm Occur" ;
VAL_ 2149547896 D2P_ALARM_HighSideUnderVolt 0 "No Alarm" 1 "Alarm Occur" ;
VAL_ 2149547896 D2P_ALARM_LowSideOverVolt 0 "No Alarm" 1 "Alarm Occur" ;
VAL_ 2149547896 D2P_ALARM_HighSideOverCurr 0 "No Alarm" 1 "Alarm Occur" ;
VAL_ 2149547896 D2P_ALARM_LowSideOverCurr_HW 0 "No Alarm" 1 "Alarm Occur" ;
VAL_ 2149547896 D2P_ALARM_LowSideOverCurr_SW 0 "No Alarm" 1 "Alarm Occur" ;
VAL_ 2149547896 D2P_ALARM_SecSideOverCurr_HW 0 "No Alarm" 1 "Alarm Occur" ;
VAL_ 2149547896 D2P_ALARM_SecSideOverCurr_SW 0 "No Alarm" 1 "Alarm Occur" ;
VAL_ 2149547896 D2P_ALARM_PriSideOverCurr_HW 0 "No Alarm" 1 "Alarm Occur" ;
VAL_ 2149547896 D2P_ALARM_PriSideOverCurr_SW 0 "No Alarm" 1 "Alarm Occur" ;
VAL_ 2149547896 D2P_ALARM_LowPowerSupplyErr 0 "No Alarm" 1 "Alarm Occur" ;
VAL_ 2149547896 D2P_ALARM_MBMUComErr 0 "No Alarm" 1 "Alarm Occur" ;
VAL_ 2149547896 D2P_ALARM_DCDCMsTeSaplgErr 0 "No Alarm" 1 "Alarm Occur" ;
VAL_ 2149547896 D2P_ALARM_DCDCTeSaplgErr 0 "No Alarm" 1 "Alarm Occur" ;
VAL_ 2149547896 D2P_ALARM_VoltSamplingErr 0 "No Alarm" 1 "Alarm Occur" ;
VAL_ 2149547896 D2P_ALARM_HgSdCuSaplgErr 0 "No Alarm" 1 "Alarm Occur" ;
VAL_ 2149547896 D2P_ALARM_CtrlCurrSamplingErr 0 "No Alarm" 1 "Alarm Occur" ;
VAL_ 2149547896 D2P_ALARM_BypassFail 0 "No Alarm" 1 "Alarm Occur" ;
VAL_ 2149547896 D2P_ALARM_Reserve1 0 "No Alarm" 1 "Alarm Occur" ;
VAL_ 2149547896 D2P_ALARM_Reserve2 0 "No Alarm" 1 "Alarm Occur" ;
VAL_ 2149547896 D2P_ALARM_Reserve3 0 "No Alarm" 1 "Alarm Occur" ;
VAL_ 2149547896 D2P_ALARM_Reserve4 0 "No Alarm" 1 "Alarm Occur" ;
VAL_ 2149547896 D2P_ALARM_Reserve5 0 "No Alarm" 1 "Alarm Occur" ;
VAL_ 2149547896 D2P_ALARM_Reserve6 0 "No Alarm" 1 "Alarm Occur" ;
VAL_ 2149547896 D2P_ALARM_Reserve7 0 "No Alarm" 1 "Alarm Occur" ;
VAL_ 2149547896 D2P_ALARM_Reserve8 0 "No Alarm" 1 "Alarm Occur" ;
VAL_ 2149547896 D2P_ALARM_Reserve9 0 "No Alarm" 1 "Alarm Occur" ;
VAL_ 2149547896 D2P_ALARM_Reserve10 0 "No Alarm" 1 "Alarm Occur" ;
VAL_ 2149547896 D2P_ALARM_Reserve11 0 "No Alarm" 1 "Alarm Occur" ;
VAL_ 2149547897 D2P_ALARM_EnvExtreOverTemp 0 "No Alarm" 1 "Alarm Occur" ;
VAL_ 2149547897 D2P_ALARM_EnvOverTemp 0 "No Alarm" 1 "Alarm Occur" ;
VAL_ 2149547897 D2P_ALARM_MosOverTemp 0 "No Alarm" 1 "Alarm Occur" ;
VAL_ 2149547897 D2P_ALARM_MosExtreOverTemp 0 "No Alarm" 1 "Alarm Occur" ;
VAL_ 2149547897 D2P_ALARM_HighSideOverVolt 0 "No Alarm" 1 "Alarm Occur" ;
VAL_ 2149547897 D2P_ALARM_HighSideUnderVolt 0 "No Alarm" 1 "Alarm Occur" ;
VAL_ 2149547897 D2P_ALARM_LowSideOverVolt 0 "No Alarm" 1 "Alarm Occur" ;
VAL_ 2149547897 D2P_ALARM_HighSideOverCurr 0 "No Alarm" 1 "Alarm Occur" ;
VAL_ 2149547897 D2P_ALARM_LowSideOverCurr_HW 0 "No Alarm" 1 "Alarm Occur" ;
VAL_ 2149547897 D2P_ALARM_LowSideOverCurr_SW 0 "No Alarm" 1 "Alarm Occur" ;
VAL_ 2149547897 D2P_ALARM_SecSideOverCurr_HW 0 "No Alarm" 1 "Alarm Occur" ;
VAL_ 2149547897 D2P_ALARM_SecSideOverCurr_SW 0 "No Alarm" 1 "Alarm Occur" ;
VAL_ 2149547897 D2P_ALARM_PriSideOverCurr_HW 0 "No Alarm" 1 "Alarm Occur" ;
VAL_ 2149547897 D2P_ALARM_PriSideOverCurr_SW 0 "No Alarm" 1 "Alarm Occur" ;
VAL_ 2149547897 D2P_ALARM_LowPowerSupplyErr 0 "No Alarm" 1 "Alarm Occur" ;
VAL_ 2149547897 D2P_ALARM_MBMUComErr 0 "No Alarm" 1 "Alarm Occur" ;
VAL_ 2149547897 D2P_ALARM_DCDCMsTeSaplgErr 0 "No Alarm" 1 "Alarm Occur" ;
VAL_ 2149547897 D2P_ALARM_DCDCTeSaplgErr 0 "No Alarm" 1 "Alarm Occur" ;
VAL_ 2149547897 D2P_ALARM_VoltSamplingErr 0 "No Alarm" 1 "Alarm Occur" ;
VAL_ 2149547897 D2P_ALARM_HgSdCuSaplgErr 0 "No Alarm" 1 "Alarm Occur" ;
VAL_ 2149547897 D2P_ALARM_CtrlCurrSamplingErr 0 "No Alarm" 1 "Alarm Occur" ;
VAL_ 2149547897 D2P_ALARM_BypassFail 0 "No Alarm" 1 "Alarm Occur" ;
VAL_ 2149547897 D2P_ALARM_Reserve1 0 "No Alarm" 1 "Alarm Occur" ;
VAL_ 2149547897 D2P_ALARM_Reserve2 0 "No Alarm" 1 "Alarm Occur" ;
VAL_ 2149547897 D2P_ALARM_Reserve3 0 "No Alarm" 1 "Alarm Occur" ;
VAL_ 2149547897 D2P_ALARM_Reserve4 0 "No Alarm" 1 "Alarm Occur" ;
VAL_ 2149547897 D2P_ALARM_Reserve5 0 "No Alarm" 1 "Alarm Occur" ;
VAL_ 2149547897 D2P_ALARM_Reserve6 0 "No Alarm" 1 "Alarm Occur" ;
VAL_ 2149547897 D2P_ALARM_Reserve7 0 "No Alarm" 1 "Alarm Occur" ;
VAL_ 2149547897 D2P_ALARM_Reserve8 0 "No Alarm" 1 "Alarm Occur" ;
VAL_ 2149547897 D2P_ALARM_Reserve9 0 "No Alarm" 1 "Alarm Occur" ;
VAL_ 2149547897 D2P_ALARM_Reserve10 0 "No Alarm" 1 "Alarm Occur" ;
VAL_ 2149547897 D2P_ALARM_Reserve11 0 "No Alarm" 1 "Alarm Occur" ;
VAL_ 2149547898 D2P_ALARM_EnvExtreOverTemp 0 "No Alarm" 1 "Alarm Occur" ;
VAL_ 2149547898 D2P_ALARM_EnvOverTemp 0 "No Alarm" 1 "Alarm Occur" ;
VAL_ 2149547898 D2P_ALARM_MosOverTemp 0 "No Alarm" 1 "Alarm Occur" ;
VAL_ 2149547898 D2P_ALARM_MosExtreOverTemp 0 "No Alarm" 1 "Alarm Occur" ;
VAL_ 2149547898 D2P_ALARM_HighSideOverVolt 0 "No Alarm" 1 "Alarm Occur" ;
VAL_ 2149547898 D2P_ALARM_HighSideUnderVolt 0 "No Alarm" 1 "Alarm Occur" ;
VAL_ 2149547898 D2P_ALARM_LowSideOverVolt 0 "No Alarm" 1 "Alarm Occur" ;
VAL_ 2149547898 D2P_ALARM_HighSideOverCurr 0 "No Alarm" 1 "Alarm Occur" ;
VAL_ 2149547898 D2P_ALARM_LowSideOverCurr_HW 0 "No Alarm" 1 "Alarm Occur" ;
VAL_ 2149547898 D2P_ALARM_LowSideOverCurr_SW 0 "No Alarm" 1 "Alarm Occur" ;
VAL_ 2149547898 D2P_ALARM_SecSideOverCurr_HW 0 "No Alarm" 1 "Alarm Occur" ;
VAL_ 2149547898 D2P_ALARM_SecSideOverCurr_SW 0 "No Alarm" 1 "Alarm Occur" ;
VAL_ 2149547898 D2P_ALARM_PriSideOverCurr_HW 0 "No Alarm" 1 "Alarm Occur" ;
VAL_ 2149547898 D2P_ALARM_PriSideOverCurr_SW 0 "No Alarm" 1 "Alarm Occur" ;
VAL_ 2149547898 D2P_ALARM_LowPowerSupplyErr 0 "No Alarm" 1 "Alarm Occur" ;
VAL_ 2149547898 D2P_ALARM_MBMUComErr 0 "No Alarm" 1 "Alarm Occur" ;
VAL_ 2149547898 D2P_ALARM_DCDCMsTeSaplgErr 0 "No Alarm" 1 "Alarm Occur" ;
VAL_ 2149547898 D2P_ALARM_DCDCTeSaplgErr 0 "No Alarm" 1 "Alarm Occur" ;
VAL_ 2149547898 D2P_ALARM_VoltSamplingErr 0 "No Alarm" 1 "Alarm Occur" ;
VAL_ 2149547898 D2P_ALARM_HgSdCuSaplgErr 0 "No Alarm" 1 "Alarm Occur" ;
VAL_ 2149547898 D2P_ALARM_CtrlCurrSamplingErr 0 "No Alarm" 1 "Alarm Occur" ;
VAL_ 2149547898 D2P_ALARM_BypassFail 0 "No Alarm" 1 "Alarm Occur" ;
VAL_ 2149547898 D2P_ALARM_Reserve1 0 "No Alarm" 1 "Alarm Occur" ;
VAL_ 2149547898 D2P_ALARM_Reserve2 0 "No Alarm" 1 "Alarm Occur" ;
VAL_ 2149547898 D2P_ALARM_Reserve3 0 "No Alarm" 1 "Alarm Occur" ;
VAL_ 2149547898 D2P_ALARM_Reserve4 0 "No Alarm" 1 "Alarm Occur" ;
VAL_ 2149547898 D2P_ALARM_Reserve5 0 "No Alarm" 1 "Alarm Occur" ;
VAL_ 2149547898 D2P_ALARM_Reserve6 0 "No Alarm" 1 "Alarm Occur" ;
VAL_ 2149547898 D2P_ALARM_Reserve7 0 "No Alarm" 1 "Alarm Occur" ;
VAL_ 2149547898 D2P_ALARM_Reserve8 0 "No Alarm" 1 "Alarm Occur" ;
VAL_ 2149547898 D2P_ALARM_Reserve9 0 "No Alarm" 1 "Alarm Occur" ;
VAL_ 2149547898 D2P_ALARM_Reserve10 0 "No Alarm" 1 "Alarm Occur" ;
VAL_ 2149547898 D2P_ALARM_Reserve11 0 "No Alarm" 1 "Alarm Occur" ;
VAL_ 2149547899 D2P_ALARM_EnvExtreOverTemp 0 "No Alarm" 1 "Alarm Occur" ;
VAL_ 2149547899 D2P_ALARM_EnvOverTemp 0 "No Alarm" 1 "Alarm Occur" ;
VAL_ 2149547899 D2P_ALARM_MosOverTemp 0 "No Alarm" 1 "Alarm Occur" ;
VAL_ 2149547899 D2P_ALARM_MosExtreOverTemp 0 "No Alarm" 1 "Alarm Occur" ;
VAL_ 2149547899 D2P_ALARM_HighSideOverVolt 0 "No Alarm" 1 "Alarm Occur" ;
VAL_ 2149547899 D2P_ALARM_HighSideUnderVolt 0 "No Alarm" 1 "Alarm Occur" ;
VAL_ 2149547899 D2P_ALARM_LowSideOverVolt 0 "No Alarm" 1 "Alarm Occur" ;
VAL_ 2149547899 D2P_ALARM_HighSideOverCurr 0 "No Alarm" 1 "Alarm Occur" ;
VAL_ 2149547899 D2P_ALARM_LowSideOverCurr_HW 0 "No Alarm" 1 "Alarm Occur" ;
VAL_ 2149547899 D2P_ALARM_LowSideOverCurr_SW 0 "No Alarm" 1 "Alarm Occur" ;
VAL_ 2149547899 D2P_ALARM_SecSideOverCurr_HW 0 "No Alarm" 1 "Alarm Occur" ;
VAL_ 2149547899 D2P_ALARM_SecSideOverCurr_SW 0 "No Alarm" 1 "Alarm Occur" ;
VAL_ 2149547899 D2P_ALARM_PriSideOverCurr_HW 0 "No Alarm" 1 "Alarm Occur" ;
VAL_ 2149547899 D2P_ALARM_PriSideOverCurr_SW 0 "No Alarm" 1 "Alarm Occur" ;
VAL_ 2149547899 D2P_ALARM_LowPowerSupplyErr 0 "No Alarm" 1 "Alarm Occur" ;
VAL_ 2149547899 D2P_ALARM_MBMUComErr 0 "No Alarm" 1 "Alarm Occur" ;
VAL_ 2149547899 D2P_ALARM_DCDCMsTeSaplgErr 0 "No Alarm" 1 "Alarm Occur" ;
VAL_ 2149547899 D2P_ALARM_DCDCTeSaplgErr 0 "No Alarm" 1 "Alarm Occur" ;
VAL_ 2149547899 D2P_ALARM_VoltSamplingErr 0 "No Alarm" 1 "Alarm Occur" ;
VAL_ 2149547899 D2P_ALARM_HgSdCuSaplgErr 0 "No Alarm" 1 "Alarm Occur" ;
VAL_ 2149547899 D2P_ALARM_CtrlCurrSamplingErr 0 "No Alarm" 1 "Alarm Occur" ;
VAL_ 2149547899 D2P_ALARM_BypassFail 0 "No Alarm" 1 "Alarm Occur" ;
VAL_ 2149547899 D2P_ALARM_Reserve1 0 "No Alarm" 1 "Alarm Occur" ;
VAL_ 2149547899 D2P_ALARM_Reserve2 0 "No Alarm" 1 "Alarm Occur" ;
VAL_ 2149547899 D2P_ALARM_Reserve3 0 "No Alarm" 1 "Alarm Occur" ;
VAL_ 2149547899 D2P_ALARM_Reserve4 0 "No Alarm" 1 "Alarm Occur" ;
VAL_ 2149547899 D2P_ALARM_Reserve5 0 "No Alarm" 1 "Alarm Occur" ;
VAL_ 2149547899 D2P_ALARM_Reserve6 0 "No Alarm" 1 "Alarm Occur" ;
VAL_ 2149547899 D2P_ALARM_Reserve7 0 "No Alarm" 1 "Alarm Occur" ;
VAL_ 2149547899 D2P_ALARM_Reserve8 0 "No Alarm" 1 "Alarm Occur" ;
VAL_ 2149547899 D2P_ALARM_Reserve9 0 "No Alarm" 1 "Alarm Occur" ;
VAL_ 2149547899 D2P_ALARM_Reserve10 0 "No Alarm" 1 "Alarm Occur" ;
VAL_ 2149547899 D2P_ALARM_Reserve11 0 "No Alarm" 1 "Alarm Occur" ;
VAL_ 2149547900 D2P_ALARM_EnvExtreOverTemp 0 "No Alarm" 1 "Alarm Occur" ;
VAL_ 2149547900 D2P_ALARM_EnvOverTemp 0 "No Alarm" 1 "Alarm Occur" ;
VAL_ 2149547900 D2P_ALARM_MosOverTemp 0 "No Alarm" 1 "Alarm Occur" ;
VAL_ 2149547900 D2P_ALARM_MosExtreOverTemp 0 "No Alarm" 1 "Alarm Occur" ;
VAL_ 2149547900 D2P_ALARM_HighSideOverVolt 0 "No Alarm" 1 "Alarm Occur" ;
VAL_ 2149547900 D2P_ALARM_HighSideUnderVolt 0 "No Alarm" 1 "Alarm Occur" ;
VAL_ 2149547900 D2P_ALARM_LowSideOverVolt 0 "No Alarm" 1 "Alarm Occur" ;
VAL_ 2149547900 D2P_ALARM_HighSideOverCurr 0 "No Alarm" 1 "Alarm Occur" ;
VAL_ 2149547900 D2P_ALARM_LowSideOverCurr_HW 0 "No Alarm" 1 "Alarm Occur" ;
VAL_ 2149547900 D2P_ALARM_LowSideOverCurr_SW 0 "No Alarm" 1 "Alarm Occur" ;
VAL_ 2149547900 D2P_ALARM_SecSideOverCurr_HW 0 "No Alarm" 1 "Alarm Occur" ;
VAL_ 2149547900 D2P_ALARM_SecSideOverCurr_SW 0 "No Alarm" 1 "Alarm Occur" ;
VAL_ 2149547900 D2P_ALARM_PriSideOverCurr_HW 0 "No Alarm" 1 "Alarm Occur" ;
VAL_ 2149547900 D2P_ALARM_PriSideOverCurr_SW 0 "No Alarm" 1 "Alarm Occur" ;
VAL_ 2149547900 D2P_ALARM_LowPowerSupplyErr 0 "No Alarm" 1 "Alarm Occur" ;
VAL_ 2149547900 D2P_ALARM_MBMUComErr 0 "No Alarm" 1 "Alarm Occur" ;
VAL_ 2149547900 D2P_ALARM_DCDCMsTeSaplgErr 0 "No Alarm" 1 "Alarm Occur" ;
VAL_ 2149547900 D2P_ALARM_DCDCTeSaplgErr 0 "No Alarm" 1 "Alarm Occur" ;
VAL_ 2149547900 D2P_ALARM_VoltSamplingErr 0 "No Alarm" 1 "Alarm Occur" ;
VAL_ 2149547900 D2P_ALARM_HgSdCuSaplgErr 0 "No Alarm" 1 "Alarm Occur" ;
VAL_ 2149547900 D2P_ALARM_CtrlCurrSamplingErr 0 "No Alarm" 1 "Alarm Occur" ;
VAL_ 2149547900 D2P_ALARM_BypassFail 0 "No Alarm" 1 "Alarm Occur" ;
VAL_ 2149547900 D2P_ALARM_Reserve1 0 "No Alarm" 1 "Alarm Occur" ;
VAL_ 2149547900 D2P_ALARM_Reserve2 0 "No Alarm" 1 "Alarm Occur" ;
VAL_ 2149547900 D2P_ALARM_Reserve3 0 "No Alarm" 1 "Alarm Occur" ;
VAL_ 2149547900 D2P_ALARM_Reserve4 0 "No Alarm" 1 "Alarm Occur" ;
VAL_ 2149547900 D2P_ALARM_Reserve5 0 "No Alarm" 1 "Alarm Occur" ;
VAL_ 2149547900 D2P_ALARM_Reserve6 0 "No Alarm" 1 "Alarm Occur" ;
VAL_ 2149547900 D2P_ALARM_Reserve7 0 "No Alarm" 1 "Alarm Occur" ;
VAL_ 2149547900 D2P_ALARM_Reserve8 0 "No Alarm" 1 "Alarm Occur" ;
VAL_ 2149547900 D2P_ALARM_Reserve9 0 "No Alarm" 1 "Alarm Occur" ;
VAL_ 2149547900 D2P_ALARM_Reserve10 0 "No Alarm" 1 "Alarm Occur" ;
VAL_ 2149547900 D2P_ALARM_Reserve11 0 "No Alarm" 1 "Alarm Occur" ;
VAL_ 2149547901 D2P_ALARM_EnvExtreOverTemp 0 "No Alarm" 1 "Alarm Occur" ;
VAL_ 2149547901 D2P_ALARM_EnvOverTemp 0 "No Alarm" 1 "Alarm Occur" ;
VAL_ 2149547901 D2P_ALARM_MosOverTemp 0 "No Alarm" 1 "Alarm Occur" ;
VAL_ 2149547901 D2P_ALARM_MosExtreOverTemp 0 "No Alarm" 1 "Alarm Occur" ;
VAL_ 2149547901 D2P_ALARM_HighSideOverVolt 0 "No Alarm" 1 "Alarm Occur" ;
VAL_ 2149547901 D2P_ALARM_HighSideUnderVolt 0 "No Alarm" 1 "Alarm Occur" ;
VAL_ 2149547901 D2P_ALARM_LowSideOverVolt 0 "No Alarm" 1 "Alarm Occur" ;
VAL_ 2149547901 D2P_ALARM_HighSideOverCurr 0 "No Alarm" 1 "Alarm Occur" ;
VAL_ 2149547901 D2P_ALARM_LowSideOverCurr_HW 0 "No Alarm" 1 "Alarm Occur" ;
VAL_ 2149547901 D2P_ALARM_LowSideOverCurr_SW 0 "No Alarm" 1 "Alarm Occur" ;
VAL_ 2149547901 D2P_ALARM_SecSideOverCurr_HW 0 "No Alarm" 1 "Alarm Occur" ;
VAL_ 2149547901 D2P_ALARM_SecSideOverCurr_SW 0 "No Alarm" 1 "Alarm Occur" ;
VAL_ 2149547901 D2P_ALARM_PriSideOverCurr_HW 0 "No Alarm" 1 "Alarm Occur" ;
VAL_ 2149547901 D2P_ALARM_PriSideOverCurr_SW 0 "No Alarm" 1 "Alarm Occur" ;
VAL_ 2149547901 D2P_ALARM_LowPowerSupplyErr 0 "No Alarm" 1 "Alarm Occur" ;
VAL_ 2149547901 D2P_ALARM_MBMUComErr 0 "No Alarm" 1 "Alarm Occur" ;
VAL_ 2149547901 D2P_ALARM_DCDCMsTeSaplgErr 0 "No Alarm" 1 "Alarm Occur" ;
VAL_ 2149547901 D2P_ALARM_DCDCTeSaplgErr 0 "No Alarm" 1 "Alarm Occur" ;
VAL_ 2149547901 D2P_ALARM_VoltSamplingErr 0 "No Alarm" 1 "Alarm Occur" ;
VAL_ 2149547901 D2P_ALARM_HgSdCuSaplgErr 0 "No Alarm" 1 "Alarm Occur" ;
VAL_ 2149547901 D2P_ALARM_CtrlCurrSamplingErr 0 "No Alarm" 1 "Alarm Occur" ;
VAL_ 2149547901 D2P_ALARM_BypassFail 0 "No Alarm" 1 "Alarm Occur" ;
VAL_ 2149547901 D2P_ALARM_Reserve1 0 "No Alarm" 1 "Alarm Occur" ;
VAL_ 2149547901 D2P_ALARM_Reserve2 0 "No Alarm" 1 "Alarm Occur" ;
VAL_ 2149547901 D2P_ALARM_Reserve3 0 "No Alarm" 1 "Alarm Occur" ;
VAL_ 2149547901 D2P_ALARM_Reserve4 0 "No Alarm" 1 "Alarm Occur" ;
VAL_ 2149547901 D2P_ALARM_Reserve5 0 "No Alarm" 1 "Alarm Occur" ;
VAL_ 2149547901 D2P_ALARM_Reserve6 0 "No Alarm" 1 "Alarm Occur" ;
VAL_ 2149547901 D2P_ALARM_Reserve7 0 "No Alarm" 1 "Alarm Occur" ;
VAL_ 2149547901 D2P_ALARM_Reserve8 0 "No Alarm" 1 "Alarm Occur" ;
VAL_ 2149547901 D2P_ALARM_Reserve9 0 "No Alarm" 1 "Alarm Occur" ;
VAL_ 2149547901 D2P_ALARM_Reserve10 0 "No Alarm" 1 "Alarm Occur" ;
VAL_ 2149547901 D2P_ALARM_Reserve11 0 "No Alarm" 1 "Alarm Occur" ;
VAL_ 2149547902 D2P_ALARM_EnvExtreOverTemp 0 "No Alarm" 1 "Alarm Occur" ;
VAL_ 2149547902 D2P_ALARM_EnvOverTemp 0 "No Alarm" 1 "Alarm Occur" ;
VAL_ 2149547902 D2P_ALARM_MosOverTemp 0 "No Alarm" 1 "Alarm Occur" ;
VAL_ 2149547902 D2P_ALARM_MosExtreOverTemp 0 "No Alarm" 1 "Alarm Occur" ;
VAL_ 2149547902 D2P_ALARM_HighSideOverVolt 0 "No Alarm" 1 "Alarm Occur" ;
VAL_ 2149547902 D2P_ALARM_HighSideUnderVolt 0 "No Alarm" 1 "Alarm Occur" ;
VAL_ 2149547902 D2P_ALARM_LowSideOverVolt 0 "No Alarm" 1 "Alarm Occur" ;
VAL_ 2149547902 D2P_ALARM_HighSideOverCurr 0 "No Alarm" 1 "Alarm Occur" ;
VAL_ 2149547902 D2P_ALARM_LowSideOverCurr_HW 0 "No Alarm" 1 "Alarm Occur" ;
VAL_ 2149547902 D2P_ALARM_LowSideOverCurr_SW 0 "No Alarm" 1 "Alarm Occur" ;
VAL_ 2149547902 D2P_ALARM_SecSideOverCurr_HW 0 "No Alarm" 1 "Alarm Occur" ;
VAL_ 2149547902 D2P_ALARM_SecSideOverCurr_SW 0 "No Alarm" 1 "Alarm Occur" ;
VAL_ 2149547902 D2P_ALARM_PriSideOverCurr_HW 0 "No Alarm" 1 "Alarm Occur" ;
VAL_ 2149547902 D2P_ALARM_PriSideOverCurr_SW 0 "No Alarm" 1 "Alarm Occur" ;
VAL_ 2149547902 D2P_ALARM_LowPowerSupplyErr 0 "No Alarm" 1 "Alarm Occur" ;
VAL_ 2149547902 D2P_ALARM_MBMUComErr 0 "No Alarm" 1 "Alarm Occur" ;
VAL_ 2149547902 D2P_ALARM_DCDCMsTeSaplgErr 0 "No Alarm" 1 "Alarm Occur" ;
VAL_ 2149547902 D2P_ALARM_DCDCTeSaplgErr 0 "No Alarm" 1 "Alarm Occur" ;
VAL_ 2149547902 D2P_ALARM_VoltSamplingErr 0 "No Alarm" 1 "Alarm Occur" ;
VAL_ 2149547902 D2P_ALARM_HgSdCuSaplgErr 0 "No Alarm" 1 "Alarm Occur" ;
VAL_ 2149547902 D2P_ALARM_CtrlCurrSamplingErr 0 "No Alarm" 1 "Alarm Occur" ;
VAL_ 2149547902 D2P_ALARM_BypassFail 0 "No Alarm" 1 "Alarm Occur" ;
VAL_ 2149547902 D2P_ALARM_Reserve1 0 "No Alarm" 1 "Alarm Occur" ;
VAL_ 2149547902 D2P_ALARM_Reserve2 0 "No Alarm" 1 "Alarm Occur" ;
VAL_ 2149547902 D2P_ALARM_Reserve3 0 "No Alarm" 1 "Alarm Occur" ;
VAL_ 2149547902 D2P_ALARM_Reserve4 0 "No Alarm" 1 "Alarm Occur" ;
VAL_ 2149547902 D2P_ALARM_Reserve5 0 "No Alarm" 1 "Alarm Occur" ;
VAL_ 2149547902 D2P_ALARM_Reserve6 0 "No Alarm" 1 "Alarm Occur" ;
VAL_ 2149547902 D2P_ALARM_Reserve7 0 "No Alarm" 1 "Alarm Occur" ;
VAL_ 2149547902 D2P_ALARM_Reserve8 0 "No Alarm" 1 "Alarm Occur" ;
VAL_ 2149547902 D2P_ALARM_Reserve9 0 "No Alarm" 1 "Alarm Occur" ;
VAL_ 2149547902 D2P_ALARM_Reserve10 0 "No Alarm" 1 "Alarm Occur" ;
VAL_ 2149547902 D2P_ALARM_Reserve11 0 "No Alarm" 1 "Alarm Occur" ;
VAL_ 2149547903 D2P_ALARM_EnvExtreOverTemp 0 "No Alarm" 1 "Alarm Occur" ;
VAL_ 2149547903 D2P_ALARM_EnvOverTemp 0 "No Alarm" 1 "Alarm Occur" ;
VAL_ 2149547903 D2P_ALARM_MosOverTemp 0 "No Alarm" 1 "Alarm Occur" ;
VAL_ 2149547903 D2P_ALARM_MosExtreOverTemp 0 "No Alarm" 1 "Alarm Occur" ;
VAL_ 2149547903 D2P_ALARM_HighSideOverVolt 0 "No Alarm" 1 "Alarm Occur" ;
VAL_ 2149547903 D2P_ALARM_HighSideUnderVolt 0 "No Alarm" 1 "Alarm Occur" ;
VAL_ 2149547903 D2P_ALARM_LowSideOverVolt 0 "No Alarm" 1 "Alarm Occur" ;
VAL_ 2149547903 D2P_ALARM_HighSideOverCurr 0 "No Alarm" 1 "Alarm Occur" ;
VAL_ 2149547903 D2P_ALARM_LowSideOverCurr_HW 0 "No Alarm" 1 "Alarm Occur" ;
VAL_ 2149547903 D2P_ALARM_LowSideOverCurr_SW 0 "No Alarm" 1 "Alarm Occur" ;
VAL_ 2149547903 D2P_ALARM_SecSideOverCurr_HW 0 "No Alarm" 1 "Alarm Occur" ;
VAL_ 2149547903 D2P_ALARM_SecSideOverCurr_SW 0 "No Alarm" 1 "Alarm Occur" ;
VAL_ 2149547903 D2P_ALARM_PriSideOverCurr_HW 0 "No Alarm" 1 "Alarm Occur" ;
VAL_ 2149547903 D2P_ALARM_PriSideOverCurr_SW 0 "No Alarm" 1 "Alarm Occur" ;
VAL_ 2149547903 D2P_ALARM_LowPowerSupplyErr 0 "No Alarm" 1 "Alarm Occur" ;
VAL_ 2149547903 D2P_ALARM_MBMUComErr 0 "No Alarm" 1 "Alarm Occur" ;
VAL_ 2149547903 D2P_ALARM_DCDCMsTeSaplgErr 0 "No Alarm" 1 "Alarm Occur" ;
VAL_ 2149547903 D2P_ALARM_DCDCTeSaplgErr 0 "No Alarm" 1 "Alarm Occur" ;
VAL_ 2149547903 D2P_ALARM_VoltSamplingErr 0 "No Alarm" 1 "Alarm Occur" ;
VAL_ 2149547903 D2P_ALARM_HgSdCuSaplgErr 0 "No Alarm" 1 "Alarm Occur" ;
VAL_ 2149547903 D2P_ALARM_CtrlCurrSamplingErr 0 "No Alarm" 1 "Alarm Occur" ;
VAL_ 2149547903 D2P_ALARM_BypassFail 0 "No Alarm" 1 "Alarm Occur" ;
VAL_ 2149547903 D2P_ALARM_Reserve1 0 "No Alarm" 1 "Alarm Occur" ;
VAL_ 2149547903 D2P_ALARM_Reserve2 0 "No Alarm" 1 "Alarm Occur" ;
VAL_ 2149547903 D2P_ALARM_Reserve3 0 "No Alarm" 1 "Alarm Occur" ;
VAL_ 2149547903 D2P_ALARM_Reserve4 0 "No Alarm" 1 "Alarm Occur" ;
VAL_ 2149547903 D2P_ALARM_Reserve5 0 "No Alarm" 1 "Alarm Occur" ;
VAL_ 2149547903 D2P_ALARM_Reserve6 0 "No Alarm" 1 "Alarm Occur" ;
VAL_ 2149547903 D2P_ALARM_Reserve7 0 "No Alarm" 1 "Alarm Occur" ;
VAL_ 2149547903 D2P_ALARM_Reserve8 0 "No Alarm" 1 "Alarm Occur" ;
VAL_ 2149547903 D2P_ALARM_Reserve9 0 "No Alarm" 1 "Alarm Occur" ;
VAL_ 2149547903 D2P_ALARM_Reserve10 0 "No Alarm" 1 "Alarm Occur" ;
VAL_ 2149547903 D2P_ALARM_Reserve11 0 "No Alarm" 1 "Alarm Occur" ;
VAL_ 2467463087 M2Sd_IDX_CMD_Type 0 "Invalid" 2 "SBMU_Code Index" 3 "DCDC_Code Index" 4 "DCDC_Confirm Index" 5 "SBMU_Confirm Index" 6 "Exit Code" 7 "Start Code" 10 "Invalid" 255 "Null" ;
VAL_ 2467463087 M2SD_IDX_SD_Index 0 "Initial Index" 1 "Index 1" 2 "Index 2" 3 "Index 3" 4 "Index 4" 5 "Index 5" 6 "Index 6" 7 "Index 7" 8 "Index 8" 9 "Index 9" 10 "Index 10" 11 "Index 11" 12 "Index 12" 13 "Index 13" 14 "Index 14" 15 "Index 15" 16 "Index 16" 17 "Index 17" 18 "Index 18" 19 "Index 19" 20 "Index 20" 21 "Index 21" 22 "Index 22" 23 "Index 23" 24 "Index 24" 25 "Index 25" 26 "Index 26" 27 "Index 27" 28 "Index 28" 29 "Index 29" 30 "Index 30" 31 "Index 31" 255 "Null" ;
VAL_ 2467463087 M2SD_SD_Result 0 "编码中" 1 "MCAN未静默" 2 "SBMU无响应" 3 "DCDC数目错误" 4 "SBMU数目错误" 5 "SBMU高压在线" 6 "SBMU匹配码错误" 7 "SBMU应答无变化" 8 "DCDC匹配吗错误" 9 "DCDC应答无变化" 10 "编码成功" ;
VAL_ 2467475265 S2M_IDX_CMD_Type_01 0 "Invalid" 1 "Request address confirmation" 2 "Reserve" 3 "Sucess" ;
VAL_ 2467475265 S2M_IDX_SBMU_Index_01 0 "Initial Index" 1 "Index 1" 2 "Index 2" 3 "Index 3" 4 "Index 4" 5 "Index 5" 6 "Index 6" 7 "Index 7" 8 "Index 8" 9 "Index 9" 10 "Index 10" 11 "Index 11" 12 "Index 12" 13 "Index 13" 14 "Index 14" 15 "Index 15" 16 "Index 16" 17 "Index 17" 18 "Index 18" 19 "Index 19" 20 "Index 20" 21 "Index 21" 22 "Index 22" 23 "Index 23" 24 "Index 24" 25 "Index 25" 26 "Index 26" 27 "Index 27" 28 "Index 28" 29 "Index 29" 30 "Index 30" 31 "Index 31" 255 "Null" ;
VAL_ 2467475265 S2M_SBMU_Result_01 0 "默认值" 1 "写入成功" 2 "写入失败" ;
VAL_ 2467475266 S2M_IDX_CMD_Type_02 0 "Invalid" 1 "Request address confirmation" 2 "Reserve" 3 "Sucess" ;
VAL_ 2467475266 S2M_IDX_SBMU_Index_02 0 "Initial Index" 1 "Index 1" 2 "Index 2" 3 "Index 3" 4 "Index 4" 5 "Index 5" 6 "Index 6" 7 "Index 7" 8 "Index 8" 9 "Index 9" 10 "Index 10" 11 "Index 11" 12 "Index 12" 13 "Index 13" 14 "Index 14" 15 "Index 15" 16 "Index 16" 17 "Index 17" 18 "Index 18" 19 "Index 19" 20 "Index 20" 21 "Index 21" 22 "Index 22" 23 "Index 23" 24 "Index 24" 25 "Index 25" 26 "Index 26" 27 "Index 27" 28 "Index 28" 29 "Index 29" 30 "Index 30" 31 "Index 31" 255 "Null" ;
VAL_ 2467475266 S2M_SBMU_Result_02 0 "默认值" 1 "写入成功" 2 "写入失败" ;
VAL_ 2467475267 S2M_IDX_CMD_Type_03 0 "Invalid" 1 "Request address confirmation" 2 "Reserve" 3 "Sucess" ;
VAL_ 2467475267 S2M_IDX_SBMU_Index_03 0 "Initial Index" 1 "Index 1" 2 "Index 2" 3 "Index 3" 4 "Index 4" 5 "Index 5" 6 "Index 6" 7 "Index 7" 8 "Index 8" 9 "Index 9" 10 "Index 10" 11 "Index 11" 12 "Index 12" 13 "Index 13" 14 "Index 14" 15 "Index 15" 16 "Index 16" 17 "Index 17" 18 "Index 18" 19 "Index 19" 20 "Index 20" 21 "Index 21" 22 "Index 22" 23 "Index 23" 24 "Index 24" 25 "Index 25" 26 "Index 26" 27 "Index 27" 28 "Index 28" 29 "Index 29" 30 "Index 30" 31 "Index 31" 255 "Null" ;
VAL_ 2467475267 S2M_SBMU_Result_03 0 "默认值" 1 "写入成功" 2 "写入失败" ;
VAL_ 2467475268 S2M_IDX_CMD_Type_04 0 "Invalid" 1 "Request address confirmation" 2 "Reserve" 3 "Sucess" ;
VAL_ 2467475268 S2M_IDX_SBMU_Index_04 0 "Initial Index" 1 "Index 1" 2 "Index 2" 3 "Index 3" 4 "Index 4" 5 "Index 5" 6 "Index 6" 7 "Index 7" 8 "Index 8" 9 "Index 9" 10 "Index 10" 11 "Index 11" 12 "Index 12" 13 "Index 13" 14 "Index 14" 15 "Index 15" 16 "Index 16" 17 "Index 17" 18 "Index 18" 19 "Index 19" 20 "Index 20" 21 "Index 21" 22 "Index 22" 23 "Index 23" 24 "Index 24" 25 "Index 25" 26 "Index 26" 27 "Index 27" 28 "Index 28" 29 "Index 29" 30 "Index 30" 31 "Index 31" 255 "Null" ;
VAL_ 2467475268 S2M_SBMU_Result_04 0 "默认值" 1 "写入成功" 2 "写入失败" ;
VAL_ 2467475269 S2M_IDX_CMD_Type_05 0 "Invalid" 1 "Request address confirmation" 2 "Reserve" 3 "Sucess" ;
VAL_ 2467475269 S2M_IDX_SBMU_Index_05 0 "Initial Index" 1 "Index 1" 2 "Index 2" 3 "Index 3" 4 "Index 4" 5 "Index 5" 6 "Index 6" 7 "Index 7" 8 "Index 8" 9 "Index 9" 10 "Index 10" 11 "Index 11" 12 "Index 12" 13 "Index 13" 14 "Index 14" 15 "Index 15" 16 "Index 16" 17 "Index 17" 18 "Index 18" 19 "Index 19" 20 "Index 20" 21 "Index 21" 22 "Index 22" 23 "Index 23" 24 "Index 24" 25 "Index 25" 26 "Index 26" 27 "Index 27" 28 "Index 28" 29 "Index 29" 30 "Index 30" 31 "Index 31" 255 "Null" ;
VAL_ 2467475269 S2M_SBMU_Result_05 0 "默认值" 1 "写入成功" 2 "写入失败" ;
VAL_ 2467475270 S2M_IDX_CMD_Type_06 0 "Invalid" 1 "Request address confirmation" 2 "Reserve" 3 "Sucess" ;
VAL_ 2467475270 S2M_IDX_SBMU_Index_06 0 "Initial Index" 1 "Index 1" 2 "Index 2" 3 "Index 3" 4 "Index 4" 5 "Index 5" 6 "Index 6" 7 "Index 7" 8 "Index 8" 9 "Index 9" 10 "Index 10" 11 "Index 11" 12 "Index 12" 13 "Index 13" 14 "Index 14" 15 "Index 15" 16 "Index 16" 17 "Index 17" 18 "Index 18" 19 "Index 19" 20 "Index 20" 21 "Index 21" 22 "Index 22" 23 "Index 23" 24 "Index 24" 25 "Index 25" 26 "Index 26" 27 "Index 27" 28 "Index 28" 29 "Index 29" 30 "Index 30" 31 "Index 31" 255 "Null" ;
VAL_ 2467475270 S2M_SBMU_Result_06 0 "默认值" 1 "写入成功" 2 "写入失败" ;
VAL_ 2467475271 S2M_IDX_CMD_Type_07 0 "Invalid" 1 "Request address confirmation" 2 "Reserve" 3 "Sucess" ;
VAL_ 2467475271 S2M_IDX_SBMU_Index_07 0 "Initial Index" 1 "Index 1" 2 "Index 2" 3 "Index 3" 4 "Index 4" 5 "Index 5" 6 "Index 6" 7 "Index 7" 8 "Index 8" 9 "Index 9" 10 "Index 10" 11 "Index 11" 12 "Index 12" 13 "Index 13" 14 "Index 14" 15 "Index 15" 16 "Index 16" 17 "Index 17" 18 "Index 18" 19 "Index 19" 20 "Index 20" 21 "Index 21" 22 "Index 22" 23 "Index 23" 24 "Index 24" 25 "Index 25" 26 "Index 26" 27 "Index 27" 28 "Index 28" 29 "Index 29" 30 "Index 30" 31 "Index 31" 255 "Null" ;
VAL_ 2467475271 S2M_SBMU_Result_07 0 "默认值" 1 "写入成功" 2 "写入失败" ;
VAL_ 2467475272 S2M_IDX_CMD_Type_08 0 "Invalid" 1 "Request address confirmation" 2 "Reserve" 3 "Sucess" ;
VAL_ 2467475272 S2M_IDX_SBMU_Index_08 0 "Initial Index" 1 "Index 1" 2 "Index 2" 3 "Index 3" 4 "Index 4" 5 "Index 5" 6 "Index 6" 7 "Index 7" 8 "Index 8" 9 "Index 9" 10 "Index 10" 11 "Index 11" 12 "Index 12" 13 "Index 13" 14 "Index 14" 15 "Index 15" 16 "Index 16" 17 "Index 17" 18 "Index 18" 19 "Index 19" 20 "Index 20" 21 "Index 21" 22 "Index 22" 23 "Index 23" 24 "Index 24" 25 "Index 25" 26 "Index 26" 27 "Index 27" 28 "Index 28" 29 "Index 29" 30 "Index 30" 31 "Index 31" 255 "Null" ;
VAL_ 2467475272 S2M_SBMU_Result_08 0 "默认值" 1 "写入成功" 2 "写入失败" ;
VAL_ 2467475273 S2M_IDX_CMD_Type_09 0 "Invalid" 1 "Request address confirmation" 2 "Reserve" 3 "Sucess" ;
VAL_ 2467475273 S2M_IDX_SBMU_Index_09 0 "Initial Index" 1 "Index 1" 2 "Index 2" 3 "Index 3" 4 "Index 4" 5 "Index 5" 6 "Index 6" 7 "Index 7" 8 "Index 8" 9 "Index 9" 10 "Index 10" 11 "Index 11" 12 "Index 12" 13 "Index 13" 14 "Index 14" 15 "Index 15" 16 "Index 16" 17 "Index 17" 18 "Index 18" 19 "Index 19" 20 "Index 20" 21 "Index 21" 22 "Index 22" 23 "Index 23" 24 "Index 24" 25 "Index 25" 26 "Index 26" 27 "Index 27" 28 "Index 28" 29 "Index 29" 30 "Index 30" 31 "Index 31" 255 "Null" ;
VAL_ 2467475273 S2M_SBMU_Result_09 0 "默认值" 1 "写入成功" 2 "写入失败" ;
VAL_ 2467475274 S2M_IDX_CMD_Type_10 0 "Invalid" 1 "Request address confirmation" 2 "Reserve" 3 "Sucess" ;
VAL_ 2467475274 S2M_IDX_SBMU_Index_10 0 "Initial Index" 1 "Index 1" 2 "Index 2" 3 "Index 3" 4 "Index 4" 5 "Index 5" 6 "Index 6" 7 "Index 7" 8 "Index 8" 9 "Index 9" 10 "Index 10" 11 "Index 11" 12 "Index 12" 13 "Index 13" 14 "Index 14" 15 "Index 15" 16 "Index 16" 17 "Index 17" 18 "Index 18" 19 "Index 19" 20 "Index 20" 21 "Index 21" 22 "Index 22" 23 "Index 23" 24 "Index 24" 25 "Index 25" 26 "Index 26" 27 "Index 27" 28 "Index 28" 29 "Index 29" 30 "Index 30" 31 "Index 31" 255 "Null" ;
VAL_ 2467475274 S2M_SBMU_Result_10 0 "默认值" 1 "写入成功" 2 "写入失败" ;
VAL_ 2467475275 S2M_IDX_CMD_Type_11 0 "Invalid" 1 "Request address confirmation" 2 "Reserve" 3 "Sucess" ;
VAL_ 2467475275 S2M_IDX_SBMU_Index_11 0 "Initial Index" 1 "Index 1" 2 "Index 2" 3 "Index 3" 4 "Index 4" 5 "Index 5" 6 "Index 6" 7 "Index 7" 8 "Index 8" 9 "Index 9" 10 "Index 10" 11 "Index 11" 12 "Index 12" 13 "Index 13" 14 "Index 14" 15 "Index 15" 16 "Index 16" 17 "Index 17" 18 "Index 18" 19 "Index 19" 20 "Index 20" 21 "Index 21" 22 "Index 22" 23 "Index 23" 24 "Index 24" 25 "Index 25" 26 "Index 26" 27 "Index 27" 28 "Index 28" 29 "Index 29" 30 "Index 30" 31 "Index 31" 255 "Null" ;
VAL_ 2467475275 S2M_SBMU_Result_11 0 "默认值" 1 "写入成功" 2 "写入失败" ;
VAL_ 2467475276 S2M_IDX_CMD_Type_12 0 "Invalid" 1 "Request address confirmation" 2 "Reserve" 3 "Sucess" ;
VAL_ 2467475276 S2M_IDX_SBMU_Index_12 0 "Initial Index" 1 "Index 1" 2 "Index 2" 3 "Index 3" 4 "Index 4" 5 "Index 5" 6 "Index 6" 7 "Index 7" 8 "Index 8" 9 "Index 9" 10 "Index 10" 11 "Index 11" 12 "Index 12" 13 "Index 13" 14 "Index 14" 15 "Index 15" 16 "Index 16" 17 "Index 17" 18 "Index 18" 19 "Index 19" 20 "Index 20" 21 "Index 21" 22 "Index 22" 23 "Index 23" 24 "Index 24" 25 "Index 25" 26 "Index 26" 27 "Index 27" 28 "Index 28" 29 "Index 29" 30 "Index 30" 31 "Index 31" 255 "Null" ;
VAL_ 2467475276 S2M_SBMU_Result_12 0 "默认值" 1 "写入成功" 2 "写入失败" ;
VAL_ 2467475277 S2M_IDX_CMD_Type_13 0 "Invalid" 1 "Request address confirmation" 2 "Reserve" 3 "Sucess" ;
VAL_ 2467475277 S2M_IDX_SBMU_Index_13 0 "Initial Index" 1 "Index 1" 2 "Index 2" 3 "Index 3" 4 "Index 4" 5 "Index 5" 6 "Index 6" 7 "Index 7" 8 "Index 8" 9 "Index 9" 10 "Index 10" 11 "Index 11" 12 "Index 12" 13 "Index 13" 14 "Index 14" 15 "Index 15" 16 "Index 16" 17 "Index 17" 18 "Index 18" 19 "Index 19" 20 "Index 20" 21 "Index 21" 22 "Index 22" 23 "Index 23" 24 "Index 24" 25 "Index 25" 26 "Index 26" 27 "Index 27" 28 "Index 28" 29 "Index 29" 30 "Index 30" 31 "Index 31" 255 "Null" ;
VAL_ 2467475277 S2M_SBMU_Result_13 0 "默认值" 1 "写入成功" 2 "写入失败" ;
VAL_ 2467475278 S2M_IDX_CMD_Type_14 0 "Invalid" 1 "Request address confirmation" 2 "Reserve" 3 "Sucess" ;
VAL_ 2467475278 S2M_IDX_SBMU_Index_14 0 "Initial Index" 1 "Index 1" 2 "Index 2" 3 "Index 3" 4 "Index 4" 5 "Index 5" 6 "Index 6" 7 "Index 7" 8 "Index 8" 9 "Index 9" 10 "Index 10" 11 "Index 11" 12 "Index 12" 13 "Index 13" 14 "Index 14" 15 "Index 15" 16 "Index 16" 17 "Index 17" 18 "Index 18" 19 "Index 19" 20 "Index 20" 21 "Index 21" 22 "Index 22" 23 "Index 23" 24 "Index 24" 25 "Index 25" 26 "Index 26" 27 "Index 27" 28 "Index 28" 29 "Index 29" 30 "Index 30" 31 "Index 31" 255 "Null" ;
VAL_ 2467475278 S2M_SBMU_Result_14 0 "默认值" 1 "写入成功" 2 "写入失败" ;
VAL_ 2467475279 S2M_IDX_CMD_Type_15 0 "Invalid" 1 "Request address confirmation" 2 "Reserve" 3 "Sucess" ;
VAL_ 2467475279 S2M_IDX_SBMU_Index_15 0 "Initial Index" 1 "Index 1" 2 "Index 2" 3 "Index 3" 4 "Index 4" 5 "Index 5" 6 "Index 6" 7 "Index 7" 8 "Index 8" 9 "Index 9" 10 "Index 10" 11 "Index 11" 12 "Index 12" 13 "Index 13" 14 "Index 14" 15 "Index 15" 16 "Index 16" 17 "Index 17" 18 "Index 18" 19 "Index 19" 20 "Index 20" 21 "Index 21" 22 "Index 22" 23 "Index 23" 24 "Index 24" 25 "Index 25" 26 "Index 26" 27 "Index 27" 28 "Index 28" 29 "Index 29" 30 "Index 30" 31 "Index 31" 255 "Null" ;
VAL_ 2467475279 S2M_SBMU_Result_15 0 "默认值" 1 "写入成功" 2 "写入失败" ;
VAL_ 2467475280 S2M_IDX_CMD_Type_16 0 "Invalid" 1 "Request address confirmation" 2 "Reserve" 3 "Sucess" ;
VAL_ 2467475280 S2M_IDX_SBMU_Index_16 0 "Initial Index" 1 "Index 1" 2 "Index 2" 3 "Index 3" 4 "Index 4" 5 "Index 5" 6 "Index 6" 7 "Index 7" 8 "Index 8" 9 "Index 9" 10 "Index 10" 11 "Index 11" 12 "Index 12" 13 "Index 13" 14 "Index 14" 15 "Index 15" 16 "Index 16" 17 "Index 17" 18 "Index 18" 19 "Index 19" 20 "Index 20" 21 "Index 21" 22 "Index 22" 23 "Index 23" 24 "Index 24" 25 "Index 25" 26 "Index 26" 27 "Index 27" 28 "Index 28" 29 "Index 29" 30 "Index 30" 31 "Index 31" 255 "Null" ;
VAL_ 2467475280 S2M_SBMU_Result_16 0 "默认值" 1 "写入成功" 2 "写入失败" ;
VERSION ""

NS_ :

BS_:

BU_: MBMU PC SBMU IMM ETH DCDC LEMS

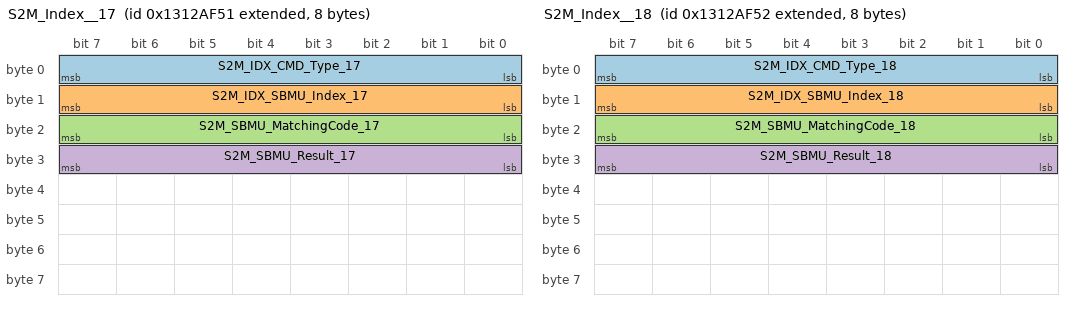
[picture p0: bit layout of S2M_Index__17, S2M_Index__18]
BO_ 2467475281 S2M_Index__17: 8 SBMU
 SG_ S2M_IDX_CMD_Type_17 : 0|8@1+ (1,0) [0|255] ""  MBMU
 SG_ S2M_IDX_SBMU_Index_17 : 8|8@1+ (1,0) [0|255] ""  MBMU
 SG_ S2M_SBMU_MatchingCode_17 : 16|8@1+ (1,0) [0|255] ""  MBMU
 SG_ S2M_SBMU_Result_17 : 24|8@1+ (1,0) [0|255] ""  MBMU

BO_ 2467475282 S2M_Index__18: 8 SBMU
 SG_ S2M_IDX_CMD_Type_18 : 0|8@1+ (1,0) [0|255] ""  MBMU
 SG_ S2M_IDX_SBMU_Index_18 : 8|8@1+ (1,0) [0|255] ""  MBMU
 SG_ S2M_SBMU_MatchingCode_18 : 16|8@1+ (1,0) [0|255] ""  MBMU
 SG_ S2M_SBMU_Result_18 : 24|8@1+ (1,0) [0|255] ""  MBMU

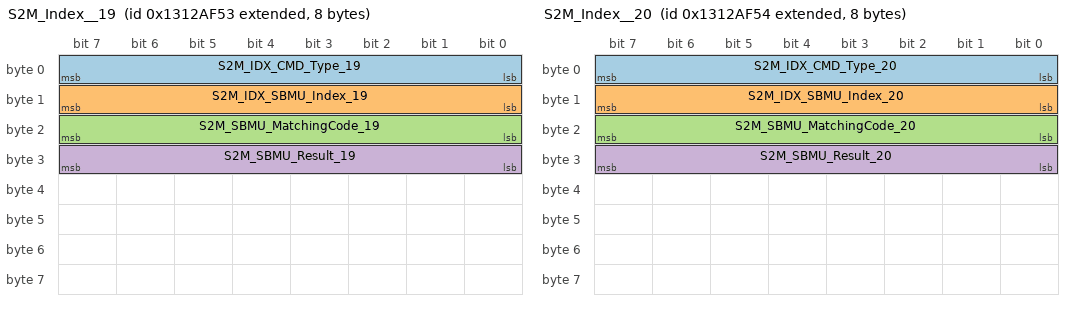
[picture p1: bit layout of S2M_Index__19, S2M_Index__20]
BO_ 2467475283 S2M_Index__19: 8 SBMU
 SG_ S2M_IDX_CMD_Type_19 : 0|8@1+ (1,0) [0|255] ""  MBMU
 SG_ S2M_IDX_SBMU_Index_19 : 8|8@1+ (1,0) [0|255] ""  MBMU
 SG_ S2M_SBMU_MatchingCode_19 : 16|8@1+ (1,0) [0|255] ""  MBMU
 SG_ S2M_SBMU_Result_19 : 24|8@1+ (1,0) [0|255] ""  MBMU

BO_ 2467475284 S2M_Index__20: 8 SBMU
 SG_ S2M_IDX_CMD_Type_20 : 0|8@1+ (1,0) [0|255] ""  MBMU
 SG_ S2M_IDX_SBMU_Index_20 : 8|8@1+ (1,0) [0|255] ""  MBMU
 SG_ S2M_SBMU_MatchingCode_20 : 16|8@1+ (1,0) [0|255] ""  MBMU
 SG_ S2M_SBMU_Result_20 : 24|8@1+ (1,0) [0|255] ""  MBMU

BO_ 2467475285 S2M_Index__21: 8 SBMU
 SG_ S2M_IDX_CMD_Type_21 : 0|8@1+ (1,0) [0|255] ""  MBMU
 SG_ S2M_IDX_SBMU_Index_21 : 8|8@1+ (1,0) [0|255] ""  MBMU
 SG_ S2M_SBMU_MatchingCode_21 : 16|8@1+ (1,0) [0|255] ""  MBMU
 SG_ S2M_SBMU_Result_21 : 24|8@1+ (1,0) [0|255] ""  MBMU

BO_ 2467475286 S2M_Index__22: 8 SBMU
 SG_ S2M_IDX_CMD_Type_22 : 0|8@1+ (1,0) [0|255] ""  MBMU
 SG_ S2M_IDX_SBMU_Index_22 : 8|8@1+ (1,0) [0|255] ""  MBMU
 SG_ S2M_SBMU_MatchingCode_22 : 16|8@1+ (1,0) [0|255] ""  MBMU
 SG_ S2M_SBMU_Result_22 : 24|8@1+ (1,0) [0|255] ""  MBMU

BO_ 2467475287 S2M_Index__23: 8 SBMU
 SG_ S2M_IDX_CMD_Type_23 : 0|8@1+ (1,0) [0|255] ""  MBMU
 SG_ S2M_IDX_SBMU_Index_23 : 8|8@1+ (1,0) [0|255] ""  MBMU
 SG_ S2M_SBMU_MatchingCode_23 : 16|8@1+ (1,0) [0|255] ""  MBMU
 SG_ S2M_SBMU_Result_23 : 24|8@1+ (1,0) [0|255] ""  MBMU

BO_ 2467475288 S2M_Index__24: 8 SBMU
 SG_ S2M_IDX_CMD_Type_24 : 0|8@1+ (1,0) [0|255] ""  MBMU
 SG_ S2M_IDX_SBMU_Index_24 : 8|8@1+ (1,0) [0|255] ""  MBMU
 SG_ S2M_SBMU_MatchingCode_24 : 16|8@1+ (1,0) [0|255] ""  MBMU
 SG_ S2M_SBMU_Result_24 : 24|8@1+ (1,0) [0|255] ""  MBMU

BO_ 2467475289 S2M_Index__25: 8 SBMU
 SG_ S2M_IDX_CMD_Type_25 : 0|8@1+ (1,0) [0|255] ""  MBMU
 SG_ S2M_IDX_SBMU_Index_25 : 8|8@1+ (1,0) [0|255] ""  MBMU
 SG_ S2M_SBMU_MatchingCode_25 : 16|8@1+ (1,0) [0|255] ""  MBMU
 SG_ S2M_SBMU_Result_25 : 24|8@1+ (1,0) [0|255] ""  MBMU

BO_ 2467475290 S2M_Index__26: 8 SBMU
 SG_ S2M_IDX_CMD_Type_26 : 0|8@1+ (1,0) [0|255] ""  MBMU
 SG_ S2M_IDX_SBMU_Index_26 : 8|8@1+ (1,0) [0|255] ""  MBMU
 SG_ S2M_SBMU_MatchingCode_26 : 16|8@1+ (1,0) [0|255] ""  MBMU
 SG_ S2M_SBMU_Result_26 : 24|8@1+ (1,0) [0|255] ""  MBMU

BO_ 2467475291 S2M_Index__27: 8 SBMU
 SG_ S2M_IDX_CMD_Type_27 : 0|8@1+ (1,0) [0|255] ""  MBMU
 SG_ S2M_IDX_SBMU_Index_27 : 8|8@1+ (1,0) [0|255] ""  MBMU
 SG_ S2M_SBMU_MatchingCode_27 : 16|8@1+ (1,0) [0|255] ""  MBMU
 SG_ S2M_SBMU_Result_27 : 24|8@1+ (1,0) [0|255] ""  MBMU

BO_ 2467475292 S2M_Index__28: 8 SBMU
 SG_ S2M_IDX_CMD_Type_28 : 0|8@1+ (1,0) [0|255] ""  MBMU
 SG_ S2M_IDX_SBMU_Index_28 : 8|8@1+ (1,0) [0|255] ""  MBMU
 SG_ S2M_SBMU_MatchingCode_28 : 16|8@1+ (1,0) [0|255] ""  MBMU
 SG_ S2M_SBMU_Result_28 : 24|8@1+ (1,0) [0|255] ""  MBMU

BO_ 2467475293 S2M_Index__29: 8 SBMU
 SG_ S2M_IDX_CMD_Type_29 : 0|8@1+ (1,0) [0|255] ""  MBMU
 SG_ S2M_IDX_SBMU_Index_29 : 8|8@1+ (1,0) [0|255] ""  MBMU
 SG_ S2M_SBMU_MatchingCode_29 : 16|8@1+ (1,0) [0|255] ""  MBMU
 SG_ S2M_SBMU_Result_29 : 24|8@1+ (1,0) [0|255] ""  MBMU

BO_ 2467475294 S2M_Index__30: 8 SBMU
 SG_ S2M_IDX_CMD_Type_30 : 0|8@1+ (1,0) [0|255] ""  MBMU
 SG_ S2M_IDX_SBMU_Index_30 : 8|8@1+ (1,0) [0|255] ""  MBMU
 SG_ S2M_SBMU_MatchingCode_30 : 16|8@1+ (1,0) [0|255] ""  MBMU
 SG_ S2M_SBMU_Result_30 : 24|8@1+ (1,0) [0|255] ""  MBMU

BO_ 2467475295 S2M_Index__31: 8 SBMU
 SG_ S2M_IDX_CMD_Type_31 : 0|8@1+ (1,0) [0|255] ""  MBMU
 SG_ S2M_IDX_SBMU_Index_31 : 8|8@1+ (1,0) [0|255] ""  MBMU
 SG_ S2M_SBMU_MatchingCode_31 : 16|8@1+ (1,0) [0|255] ""  MBMU
 SG_ S2M_SBMU_Result_31 : 24|8@1+ (1,0) [0|255] ""  MBMU

BO_ 2467475296 S2M_Index__32: 8 SBMU
 SG_ S2M_IDX_CMD_Type_32 : 0|8@1+ (1,0) [0|255] ""  MBMU
 SG_ S2M_IDX_SBMU_Index_32 : 8|8@1+ (1,0) [0|255] ""  MBMU
 SG_ S2M_SBMU_MatchingCode_32 : 16|8@1+ (1,0) [0|255] ""  MBMU
 SG_ S2M_SBMU_Result_32 : 24|8@1+ (1,0) [0|255] ""  MBMU

BO_ 2467475297 S2M_Index__33: 8 SBMU
 SG_ S2M_IDX_CMD_Type_33 : 0|8@1+ (1,0) [0|255] ""  MBMU
 SG_ S2M_IDX_SBMU_Index_33 : 8|8@1+ (1,0) [0|255] ""  MBMU
 SG_ S2M_SBMU_MatchingCode_33 : 16|8@1+ (1,0) [0|255] ""  MBMU
 SG_ S2M_SBMU_Result_33 : 24|8@1+ (1,0) [0|255] ""  MBMU

BO_ 2467475298 S2M_Index__34: 8 SBMU
 SG_ S2M_IDX_CMD_Type_34 : 0|8@1+ (1,0) [0|255] ""  MBMU
 SG_ S2M_IDX_SBMU_Index_34 : 8|8@1+ (1,0) [0|255] ""  MBMU
 SG_ S2M_SBMU_MatchingCode_34 : 16|8@1+ (1,0) [0|255] ""  MBMU
 SG_ S2M_SBMU_Result_34 : 24|8@1+ (1,0) [0|255] ""  MBMU

BO_ 2467475299 S2M_Index__35: 8 SBMU
 SG_ S2M_IDX_CMD_Type_35 : 0|8@1+ (1,0) [0|255] ""  MBMU
 SG_ S2M_IDX_SBMU_Index_35 : 8|8@1+ (1,0) [0|255] ""  MBMU
 SG_ S2M_SBMU_MatchingCode_35 : 16|8@1+ (1,0) [0|255] ""  MBMU
 SG_ S2M_SBMU_Result_35 : 24|8@1+ (1,0) [0|255] ""  MBMU

BO_ 2467475300 S2M_Index__36: 8 SBMU
 SG_ S2M_IDX_CMD_Type_36 : 0|8@1+ (1,0) [0|255] ""  MBMU
 SG_ S2M_IDX_SBMU_Index_36 : 8|8@1+ (1,0) [0|255] ""  MBMU
 SG_ S2M_SBMU_MatchingCode_36 : 16|8@1+ (1,0) [0|255] ""  MBMU
 SG_ S2M_SBMU_Result_36 : 24|8@1+ (1,0) [0|255] ""  MBMU

BO_ 2467475301 S2M_Index__37: 8 SBMU
 SG_ S2M_IDX_CMD_Type_37 : 0|8@1+ (1,0) [0|255] ""  MBMU
 SG_ S2M_IDX_SBMU_Index_37 : 8|8@1+ (1,0) [0|255] ""  MBMU
 SG_ S2M_SBMU_MatchingCode_37 : 16|8@1+ (1,0) [0|255] ""  MBMU
 SG_ S2M_SBMU_Result_37 : 24|8@1+ (1,0) [0|255] ""  MBMU

BO_ 2467475302 S2M_Index__38: 8 SBMU
 SG_ S2M_IDX_CMD_Type_38 : 0|8@1+ (1,0) [0|255] ""  MBMU
 SG_ S2M_IDX_SBMU_Index_38 : 8|8@1+ (1,0) [0|255] ""  MBMU
 SG_ S2M_SBMU_MatchingCode_38 : 16|8@1+ (1,0) [0|255] ""  MBMU
 SG_ S2M_SBMU_Result_38 : 24|8@1+ (1,0) [0|255] ""  MBMU

BO_ 2467475303 S2M_Index__39: 8 SBMU
 SG_ S2M_IDX_CMD_Type_39 : 0|8@1+ (1,0) [0|255] ""  MBMU
 SG_ S2M_IDX_SBMU_Index_39 : 8|8@1+ (1,0) [0|255] ""  MBMU
 SG_ S2M_SBMU_MatchingCode_39 : 16|8@1+ (1,0) [0|255] ""  MBMU
 SG_ S2M_SBMU_Result_39 : 24|8@1+ (1,0) [0|255] ""  MBMU

BO_ 2467475304 S2M_Index__40: 8 SBMU
 SG_ S2M_IDX_CMD_Type_40 : 0|8@1+ (1,0) [0|255] ""  MBMU
 SG_ S2M_IDX_SBMU_Index_40 : 8|8@1+ (1,0) [0|255] ""  MBMU
 SG_ S2M_SBMU_MatchingCode_40 : 16|8@1+ (1,0) [0|255] ""  MBMU
 SG_ S2M_SBMU_Result_40 : 24|8@1+ (1,0) [0|255] ""  MBMU

BO_ 2467475305 S2M_Index__41: 8 SBMU
 SG_ S2M_IDX_CMD_Type_41 : 0|8@1+ (1,0) [0|255] ""  MBMU
 SG_ S2M_IDX_SBMU_Index_41 : 8|8@1+ (1,0) [0|255] ""  MBMU
 SG_ S2M_SBMU_MatchingCode_41 : 16|8@1+ (1,0) [0|255] ""  MBMU
 SG_ S2M_SBMU_Result_41 : 24|8@1+ (1,0) [0|255] ""  MBMU

BO_ 2467475306 S2M_Index__42: 8 SBMU
 SG_ S2M_IDX_CMD_Type_42 : 0|8@1+ (1,0) [0|255] ""  MBMU
 SG_ S2M_IDX_SBMU_Index_42 : 8|8@1+ (1,0) [0|255] ""  MBMU
 SG_ S2M_SBMU_MatchingCode_42 : 16|8@1+ (1,0) [0|255] ""  MBMU
 SG_ S2M_SBMU_Result_42 : 24|8@1+ (1,0) [0|255] ""  MBMU

BO_ 2467475307 S2M_Index__43: 8 SBMU
 SG_ S2M_IDX_CMD_Type_43 : 0|8@1+ (1,0) [0|255] ""  MBMU
 SG_ S2M_IDX_SBMU_Index_43 : 8|8@1+ (1,0) [0|255] ""  MBMU
 SG_ S2M_SBMU_MatchingCode_43 : 16|8@1+ (1,0) [0|255] ""  MBMU
 SG_ S2M_SBMU_Result_43 : 24|8@1+ (1,0) [0|255] ""  MBMU

BO_ 2467475308 S2M_Index__44: 8 SBMU
 SG_ S2M_IDX_CMD_Type_44 : 0|8@1+ (1,0) [0|255] ""  MBMU
 SG_ S2M_IDX_SBMU_Index_44 : 8|8@1+ (1,0) [0|255] ""  MBMU
 SG_ S2M_SBMU_MatchingCode_44 : 16|8@1+ (1,0) [0|255] ""  MBMU
 SG_ S2M_SBMU_Result_44 : 24|8@1+ (1,0) [0|255] ""  MBMU

BO_ 2467475309 S2M_Index__45: 8 SBMU
 SG_ S2M_IDX_CMD_Type_45 : 0|8@1+ (1,0) [0|255] ""  MBMU
 SG_ S2M_IDX_SBMU_Index_45 : 8|8@1+ (1,0) [0|255] ""  MBMU
 SG_ S2M_SBMU_MatchingCode_45 : 16|8@1+ (1,0) [0|255] ""  MBMU
 SG_ S2M_SBMU_Result_45 : 24|8@1+ (1,0) [0|255] ""  MBMU

BO_ 2467475310 S2M_Index__46: 8 SBMU
 SG_ S2M_IDX_CMD_Type_46 : 0|8@1+ (1,0) [0|255] ""  MBMU
 SG_ S2M_IDX_SBMU_Index_46 : 8|8@1+ (1,0) [0|255] ""  MBMU
 SG_ S2M_SBMU_MatchingCode_46 : 16|8@1+ (1,0) [0|255] ""  MBMU
 SG_ S2M_SBMU_Result_46 : 24|8@1+ (1,0) [0|255] ""  MBMU

BO_ 2467475311 S2M_Index__47: 8 SBMU
 SG_ S2M_IDX_CMD_Type_47 : 0|8@1+ (1,0) [0|255] ""  MBMU
 SG_ S2M_IDX_SBMU_Index_47 : 8|8@1+ (1,0) [0|255] ""  MBMU
 SG_ S2M_SBMU_MatchingCode_47 : 16|8@1+ (1,0) [0|255] ""  MBMU
 SG_ S2M_SBMU_Result_47 : 24|8@1+ (1,0) [0|255] ""  MBMU

BO_ 2467475312 S2M_Index__48: 8 SBMU
 SG_ S2M_IDX_CMD_Type_48 : 0|8@1+ (1,0) [0|255] ""  MBMU
 SG_ S2M_IDX_SBMU_Index_48 : 8|8@1+ (1,0) [0|255] ""  MBMU
 SG_ S2M_SBMU_MatchingCode_48 : 16|8@1+ (1,0) [0|255] ""  MBMU
 SG_ S2M_SBMU_Result_48 : 24|8@1+ (1,0) [0|255] ""  MBMU

BO_ 2467475313 S2M_Index__49: 8 SBMU
 SG_ S2M_IDX_CMD_Type_49 : 0|8@1+ (1,0) [0|255] ""  MBMU
 SG_ S2M_IDX_SBMU_Index_49 : 8|8@1+ (1,0) [0|255] ""  MBMU
 SG_ S2M_SBMU_MatchingCode_49 : 16|8@1+ (1,0) [0|255] ""  MBMU
 SG_ S2M_SBMU_Result_49 : 24|8@1+ (1,0) [0|255] ""  MBMU

BO_ 2467475314 S2M_Index__50: 8 SBMU
 SG_ S2M_IDX_CMD_Type_50 : 0|8@1+ (1,0) [0|255] ""  MBMU
 SG_ S2M_IDX_SBMU_Index_50 : 8|8@1+ (1,0) [0|255] ""  MBMU
 SG_ S2M_SBMU_MatchingCode_50 : 16|8@1+ (1,0) [0|255] ""  MBMU
 SG_ S2M_SBMU_Result_50 : 24|8@1+ (1,0) [0|255] ""  MBMU

BO_ 2467475315 S2M_Index__51: 8 SBMU
 SG_ S2M_IDX_CMD_Type_51 : 0|8@1+ (1,0) [0|255] ""  MBMU
 SG_ S2M_IDX_SBMU_Index_51 : 8|8@1+ (1,0) [0|255] ""  MBMU
 SG_ S2M_SBMU_MatchingCode_51 : 16|8@1+ (1,0) [0|255] ""  MBMU
 SG_ S2M_SBMU_Result_51 : 24|8@1+ (1,0) [0|255] ""  MBMU

BO_ 2467475316 S2M_Index__52: 8 SBMU
 SG_ S2M_IDX_CMD_Type_52 : 0|8@1+ (1,0) [0|255] ""  MBMU
 SG_ S2M_IDX_SBMU_Index_52 : 8|8@1+ (1,0) [0|255] ""  MBMU
 SG_ S2M_SBMU_MatchingCode_52 : 16|8@1+ (1,0) [0|255] ""  MBMU
 SG_ S2M_SBMU_Result_52 : 24|8@1+ (1,0) [0|255] ""  MBMU

BO_ 2467475317 S2M_Index__53: 8 SBMU
 SG_ S2M_IDX_CMD_Type_53 : 0|8@1+ (1,0) [0|255] ""  MBMU
 SG_ S2M_IDX_SBMU_Index_53 : 8|8@1+ (1,0) [0|255] ""  MBMU
 SG_ S2M_SBMU_MatchingCode_53 : 16|8@1+ (1,0) [0|255] ""  MBMU
 SG_ S2M_SBMU_Result_53 : 24|8@1+ (1,0) [0|255] ""  MBMU

BO_ 2467475318 S2M_Index__54: 8 SBMU
 SG_ S2M_IDX_CMD_Type_54 : 0|8@1+ (1,0) [0|255] ""  MBMU
 SG_ S2M_IDX_SBMU_Index_54 : 8|8@1+ (1,0) [0|255] ""  MBMU
 SG_ S2M_SBMU_MatchingCode_54 : 16|8@1+ (1,0) [0|255] ""  MBMU
 SG_ S2M_SBMU_Result_54 : 24|8@1+ (1,0) [0|255] ""  MBMU

BO_ 2467475319 S2M_Index__55: 8 SBMU
 SG_ S2M_IDX_CMD_Type_55 : 0|8@1+ (1,0) [0|255] ""  MBMU
 SG_ S2M_IDX_SBMU_Index_55 : 8|8@1+ (1,0) [0|255] ""  MBMU
 SG_ S2M_SBMU_MatchingCode_55 : 16|8@1+ (1,0) [0|255] ""  MBMU
 SG_ S2M_SBMU_Result_55 : 24|8@1+ (1,0) [0|255] ""  MBMU

BO_ 2467475320 S2M_Index__56: 8 SBMU
 SG_ S2M_IDX_CMD_Type_56 : 0|8@1+ (1,0) [0|255] ""  MBMU
 SG_ S2M_IDX_SBMU_Index_56 : 8|8@1+ (1,0) [0|255] ""  MBMU
 SG_ S2M_SBMU_MatchingCode_56 : 16|8@1+ (1,0) [0|255] ""  MBMU
 SG_ S2M_SBMU_Result_56 : 24|8@1+ (1,0) [0|255] ""  MBMU

BO_ 2467475321 S2M_Index__57: 8 SBMU
 SG_ S2M_IDX_CMD_Type_57 : 0|8@1+ (1,0) [0|255] ""  MBMU
 SG_ S2M_IDX_SBMU_Index_57 : 8|8@1+ (1,0) [0|255] ""  MBMU
 SG_ S2M_SBMU_MatchingCode_57 : 16|8@1+ (1,0) [0|255] ""  MBMU
 SG_ S2M_SBMU_Result_57 : 24|8@1+ (1,0) [0|255] ""  MBMU

BO_ 2467475322 S2M_Index__58: 8 SBMU
 SG_ S2M_IDX_CMD_Type_58 : 0|8@1+ (1,0) [0|255] ""  MBMU
 SG_ S2M_IDX_SBMU_Index_58 : 8|8@1+ (1,0) [0|255] ""  MBMU
 SG_ S2M_SBMU_MatchingCode_58 : 16|8@1+ (1,0) [0|255] ""  MBMU
 SG_ S2M_SBMU_Result_58 : 24|8@1+ (1,0) [0|255] ""  MBMU

BO_ 2467475323 S2M_Index__59: 8 SBMU
 SG_ S2M_IDX_CMD_Type_59 : 0|8@1+ (1,0) [0|255] ""  MBMU
 SG_ S2M_IDX_SBMU_Index_59 : 8|8@1+ (1,0) [0|255] ""  MBMU
 SG_ S2M_SBMU_MatchingCode_59 : 16|8@1+ (1,0) [0|255] ""  MBMU
 SG_ S2M_SBMU_Result_59 : 24|8@1+ (1,0) [0|255] ""  MBMU

BO_ 2467475324 S2M_Index__60: 8 SBMU
 SG_ S2M_IDX_CMD_Type_60 : 0|8@1+ (1,0) [0|255] ""  MBMU
 SG_ S2M_IDX_SBMU_Index_60 : 8|8@1+ (1,0) [0|255] ""  MBMU
 SG_ S2M_SBMU_MatchingCode_60 : 16|8@1+ (1,0) [0|255] ""  MBMU
 SG_ S2M_SBMU_Result_60 : 24|8@1+ (1,0) [0|255] ""  MBMU

BO_ 2467475325 S2M_Index__61: 8 SBMU
 SG_ S2M_IDX_CMD_Type_61 : 0|8@1+ (1,0) [0|255] ""  MBMU
 SG_ S2M_IDX_SBMU_Index_61 : 8|8@1+ (1,0) [0|255] ""  MBMU
 SG_ S2M_SBMU_MatchingCode_61 : 16|8@1+ (1,0) [0|255] ""  MBMU
 SG_ S2M_SBMU_Result_61 : 24|8@1+ (1,0) [0|255] ""  MBMU

BO_ 2467475326 S2M_Index__62: 8 SBMU
 SG_ S2M_IDX_CMD_Type_62 : 0|8@1+ (1,0) [0|255] ""  MBMU
 SG_ S2M_IDX_SBMU_Index_62 : 8|8@1+ (1,0) [0|255] ""  MBMU
 SG_ S2M_SBMU_MatchingCode_62 : 16|8@1+ (1,0) [0|255] ""  MBMU
 SG_ S2M_SBMU_Result_62 : 24|8@1+ (1,0) [0|255] ""  MBMU

BO_ 2467475327 S2M_Index__63: 8 SBMU
 SG_ S2M_IDX_CMD_Type_63 : 0|8@1+ (1,0) [0|255] ""  MBMU
 SG_ S2M_IDX_SBMU_Index_63 : 8|8@1+ (1,0) [0|255] ""  MBMU
 SG_ S2M_SBMU_MatchingCode_63 : 16|8@1+ (1,0) [0|255] ""  MBMU
 SG_ S2M_SBMU_Result_63 : 24|8@1+ (1,0) [0|255] ""  MBMU

BO_ 2467540801 D2M_Index__01: 8 DCDC
 SG_ D2M_IDX_CMD_Type_01 : 0|8@1+ (1,0) [0|255] ""  MBMU
 SG_ D2M_IDX_DCDC_Index_01 : 8|8@1+ (1,0) [0|255] ""  MBMU
 SG_ D2M_DCDC_MatchingCode_01 : 16|8@1+ (1,0) [0|255] ""  MBMU
 SG_ D2M_DCDC_Result_01 : 24|8@1+ (1,0) [0|255] ""  MBMU

BO_ 2467540802 D2M_Index__02: 8 DCDC
 SG_ D2M_IDX_CMD_Type_02 : 0|8@1+ (1,0) [0|255] ""  MBMU
 SG_ D2M_IDX_DCDC_Index_02 : 8|8@1+ (1,0) [0|255] ""  MBMU
 SG_ D2M_DCDC_MatchingCode_02 : 16|8@1+ (1,0) [0|255] ""  MBMU
 SG_ D2M_DCDC_Result_02 : 24|8@1+ (1,0) [0|255] ""  MBMU

BO_ 2467540803 D2M_Index__03: 8 DCDC
 SG_ D2M_IDX_CMD_Type_03 : 0|8@1+ (1,0) [0|255] ""  MBMU
 SG_ D2M_IDX_DCDC_Index_03 : 8|8@1+ (1,0) [0|255] ""  MBMU
 SG_ D2M_DCDC_MatchingCode_03 : 16|8@1+ (1,0) [0|255] ""  MBMU
 SG_ D2M_DCDC_Result_03 : 24|8@1+ (1,0) [0|255] ""  MBMU

BO_ 2467540804 D2M_Index__04: 8 DCDC
 SG_ D2M_IDX_CMD_Type_04 : 0|8@1+ (1,0) [0|255] ""  MBMU
 SG_ D2M_IDX_DCDC_Index_04 : 8|8@1+ (1,0) [0|255] ""  MBMU
 SG_ D2M_DCDC_MatchingCode_04 : 16|8@1+ (1,0) [0|255] ""  MBMU
 SG_ D2M_DCDC_Result_04 : 24|8@1+ (1,0) [0|255] ""  MBMU

BO_ 2467540805 D2M_Index__05: 8 DCDC
 SG_ D2M_IDX_CMD_Type_05 : 0|8@1+ (1,0) [0|255] ""  MBMU
 SG_ D2M_IDX_DCDC_Index_05 : 8|8@1+ (1,0) [0|255] ""  MBMU
 SG_ D2M_DCDC_MatchingCode_05 : 16|8@1+ (1,0) [0|255] ""  MBMU
 SG_ D2M_DCDC_Result_05 : 24|8@1+ (1,0) [0|255] ""  MBMU

BO_ 2467540806 D2M_Index__06: 8 DCDC
 SG_ D2M_IDX_CMD_Type_06 : 0|8@1+ (1,0) [0|255] ""  MBMU
 SG_ D2M_IDX_DCDC_Index_06 : 8|8@1+ (1,0) [0|255] ""  MBMU
 SG_ D2M_DCDC_MatchingCode_06 : 16|8@1+ (1,0) [0|255] ""  MBMU
 SG_ D2M_DCDC_Result_06 : 24|8@1+ (1,0) [0|255] ""  MBMU

BO_ 2467540807 D2M_Index__07: 8 DCDC
 SG_ D2M_IDX_CMD_Type_07 : 0|8@1+ (1,0) [0|255] ""  MBMU
 SG_ D2M_IDX_DCDC_Index_07 : 8|8@1+ (1,0) [0|255] ""  MBMU
 SG_ D2M_DCDC_MatchingCode_07 : 16|8@1+ (1,0) [0|255] ""  MBMU
 SG_ D2M_DCDC_Result_07 : 24|8@1+ (1,0) [0|255] ""  MBMU

BO_ 2467540808 D2M_Index__08: 8 DCDC
 SG_ D2M_IDX_CMD_Type_08 : 0|8@1+ (1,0) [0|255] ""  MBMU
 SG_ D2M_IDX_DCDC_Index_08 : 8|8@1+ (1,0) [0|255] ""  MBMU
 SG_ D2M_DCDC_MatchingCode_08 : 16|8@1+ (1,0) [0|255] ""  MBMU
 SG_ D2M_DCDC_Result_08 : 24|8@1+ (1,0) [0|255] ""  MBMU

BO_ 2467540809 D2M_Index__09: 8 DCDC
 SG_ D2M_IDX_CMD_Type_09 : 0|8@1+ (1,0) [0|255] ""  MBMU
 SG_ D2M_IDX_DCDC_Index_09 : 8|8@1+ (1,0) [0|255] ""  MBMU
 SG_ D2M_DCDC_MatchingCode_09 : 16|8@1+ (1,0) [0|255] ""  MBMU
 SG_ D2M_DCDC_Result_09 : 24|8@1+ (1,0) [0|255] ""  MBMU

BO_ 2467540810 D2M_Index__10: 8 DCDC
 SG_ D2M_IDX_CMD_Type_10 : 0|8@1+ (1,0) [0|255] ""  MBMU
 SG_ D2M_IDX_DCDC_Index_10 : 8|8@1+ (1,0) [0|255] ""  MBMU
 SG_ D2M_DCDC_MatchingCode_10 : 16|8@1+ (1,0) [0|255] ""  MBMU
 SG_ D2M_DCDC_Result_10 : 24|8@1+ (1,0) [0|255] ""  MBMU

BO_ 2467540811 D2M_Index__11: 8 DCDC
 SG_ D2M_IDX_CMD_Type_11 : 0|8@1+ (1,0) [0|255] ""  MBMU
 SG_ D2M_IDX_DCDC_Index_11 : 8|8@1+ (1,0) [0|255] ""  MBMU
 SG_ D2M_DCDC_MatchingCode_11 : 16|8@1+ (1,0) [0|255] ""  MBMU
 SG_ D2M_DCDC_Result_11 : 24|8@1+ (1,0) [0|255] ""  MBMU

BO_ 2467540812 D2M_Index__12: 8 DCDC
 SG_ D2M_IDX_CMD_Type_12 : 0|8@1+ (1,0) [0|255] ""  MBMU
 SG_ D2M_IDX_DCDC_Index_12 : 8|8@1+ (1,0) [0|255] ""  MBMU
 SG_ D2M_DCDC_MatchingCode_12 : 16|8@1+ (1,0) [0|255] ""  MBMU
 SG_ D2M_DCDC_Result_12 : 24|8@1+ (1,0) [0|255] ""  MBMU

BO_ 2467540813 D2M_Index__13: 8 DCDC
 SG_ D2M_IDX_CMD_Type_13 : 0|8@1+ (1,0) [0|255] ""  MBMU
 SG_ D2M_IDX_DCDC_Index_13 : 8|8@1+ (1,0) [0|255] ""  MBMU
 SG_ D2M_DCDC_MatchingCode_13 : 16|8@1+ (1,0) [0|255] ""  MBMU
 SG_ D2M_DCDC_Result_13 : 24|8@1+ (1,0) [0|255] ""  MBMU

BO_ 2467540814 D2M_Index__14: 8 DCDC
 SG_ D2M_IDX_CMD_Type_14 : 0|8@1+ (1,0) [0|255] ""  MBMU
 SG_ D2M_IDX_DCDC_Index_14 : 8|8@1+ (1,0) [0|255] ""  MBMU
 SG_ D2M_DCDC_MatchingCode_14 : 16|8@1+ (1,0) [0|255] ""  MBMU
 SG_ D2M_DCDC_Result_14 : 24|8@1+ (1,0) [0|255] ""  MBMU

BO_ 2467540815 D2M_Index__15: 8 DCDC
 SG_ D2M_IDX_CMD_Type_15 : 0|8@1+ (1,0) [0|255] ""  MBMU
 SG_ D2M_IDX_DCDC_Index_15 : 8|8@1+ (1,0) [0|255] ""  MBMU
 SG_ D2M_DCDC_MatchingCode_15 : 16|8@1+ (1,0) [0|255] ""  MBMU
 SG_ D2M_DCDC_Result_15 : 24|8@1+ (1,0) [0|255] ""  MBMU

BO_ 2467540816 D2M_Index__16: 8 DCDC
 SG_ D2M_IDX_CMD_Type_16 : 0|8@1+ (1,0) [0|255] ""  MBMU
 SG_ D2M_IDX_DCDC_Index_16 : 8|8@1+ (1,0) [0|255] ""  MBMU
 SG_ D2M_DCDC_MatchingCode_16 : 16|8@1+ (1,0) [0|255] ""  MBMU
 SG_ D2M_DCDC_Result_16 : 24|8@1+ (1,0) [0|255] ""  MBMU

BO_ 2467540817 D2M_Index__17: 8 DCDC
 SG_ D2M_IDX_CMD_Type_17 : 0|8@1+ (1,0) [0|255] ""  MBMU
 SG_ D2M_IDX_DCDC_Index_17 : 8|8@1+ (1,0) [0|255] ""  MBMU
 SG_ D2M_DCDC_MatchingCode_17 : 16|8@1+ (1,0) [0|255] ""  MBMU
 SG_ D2M_DCDC_Result_17 : 24|8@1+ (1,0) [0|255] ""  MBMU

BO_ 2467540818 D2M_Index__18: 8 DCDC
 SG_ D2M_IDX_CMD_Type_18 : 0|8@1+ (1,0) [0|255] ""  MBMU
 SG_ D2M_IDX_DCDC_Index_18 : 8|8@1+ (1,0) [0|255] ""  MBMU
 SG_ D2M_DCDC_MatchingCode_18 : 16|8@1+ (1,0) [0|255] ""  MBMU
 SG_ D2M_DCDC_Result_18 : 24|8@1+ (1,0) [0|255] ""  MBMU

BO_ 2467540819 D2M_Index__19: 8 DCDC
 SG_ D2M_IDX_CMD_Type_19 : 0|8@1+ (1,0) [0|255] ""  MBMU
 SG_ D2M_IDX_DCDC_Index_19 : 8|8@1+ (1,0) [0|255] ""  MBMU
 SG_ D2M_DCDC_MatchingCode_19 : 16|8@1+ (1,0) [0|255] ""  MBMU
 SG_ D2M_DCDC_Result_19 : 24|8@1+ (1,0) [0|255] ""  MBMU

BO_ 2467540820 D2M_Index__20: 8 DCDC
 SG_ D2M_IDX_CMD_Type_20 : 0|8@1+ (1,0) [0|255] ""  MBMU
 SG_ D2M_IDX_DCDC_Index_20 : 8|8@1+ (1,0) [0|255] ""  MBMU
 SG_ D2M_DCDC_MatchingCode_20 : 16|8@1+ (1,0) [0|255] ""  MBMU
 SG_ D2M_DCDC_Result_20 : 24|8@1+ (1,0) [0|255] ""  MBMU

BO_ 2467540821 D2M_Index__21: 8 DCDC
 SG_ D2M_IDX_CMD_Type_21 : 0|8@1+ (1,0) [0|255] ""  MBMU
 SG_ D2M_IDX_DCDC_Index_21 : 8|8@1+ (1,0) [0|255] ""  MBMU
 SG_ D2M_DCDC_MatchingCode_21 : 16|8@1+ (1,0) [0|255] ""  MBMU
 SG_ D2M_DCDC_Result_21 : 24|8@1+ (1,0) [0|255] ""  MBMU

BO_ 2467540822 D2M_Index__22: 8 DCDC
 SG_ D2M_IDX_CMD_Type_22 : 0|8@1+ (1,0) [0|255] ""  MBMU
 SG_ D2M_IDX_DCDC_Index_22 : 8|8@1+ (1,0) [0|255] ""  MBMU
 SG_ D2M_DCDC_MatchingCode_22 : 16|8@1+ (1,0) [0|255] ""  MBMU
 SG_ D2M_DCDC_Result_22 : 24|8@1+ (1,0) [0|255] ""  MBMU

BO_ 2467540823 D2M_Index__23: 8 DCDC
 SG_ D2M_IDX_CMD_Type_23 : 0|8@1+ (1,0) [0|255] ""  MBMU
 SG_ D2M_IDX_DCDC_Index_23 : 8|8@1+ (1,0) [0|255] ""  MBMU
 SG_ D2M_DCDC_MatchingCode_23 : 16|8@1+ (1,0) [0|255] ""  MBMU
 SG_ D2M_DCDC_Result_23 : 24|8@1+ (1,0) [0|255] ""  MBMU

BO_ 2467540824 D2M_Index__24: 8 DCDC
 SG_ D2M_IDX_CMD_Type_24 : 0|8@1+ (1,0) [0|255] ""  MBMU
 SG_ D2M_IDX_DCDC_Index_24 : 8|8@1+ (1,0) [0|255] ""  MBMU
 SG_ D2M_DCDC_MatchingCode_24 : 16|8@1+ (1,0) [0|255] ""  MBMU
 SG_ D2M_DCDC_Result_24 : 24|8@1+ (1,0) [0|255] ""  MBMU

BO_ 2467540825 D2M_Index__25: 8 DCDC
 SG_ D2M_IDX_CMD_Type_25 : 0|8@1+ (1,0) [0|255] ""  MBMU
 SG_ D2M_IDX_DCDC_Index_25 : 8|8@1+ (1,0) [0|255] ""  MBMU
 SG_ D2M_DCDC_MatchingCode_25 : 16|8@1+ (1,0) [0|255] ""  MBMU
 SG_ D2M_DCDC_Result_25 : 24|8@1+ (1,0) [0|255] ""  MBMU

BO_ 2467540826 D2M_Index__26: 8 DCDC
 SG_ D2M_IDX_CMD_Type_26 : 0|8@1+ (1,0) [0|255] ""  MBMU
 SG_ D2M_IDX_DCDC_Index_26 : 8|8@1+ (1,0) [0|255] ""  MBMU
 SG_ D2M_DCDC_MatchingCode_26 : 16|8@1+ (1,0) [0|255] ""  MBMU
 SG_ D2M_DCDC_Result_26 : 24|8@1+ (1,0) [0|255] ""  MBMU

BO_ 2467540827 D2M_Index__27: 8 DCDC
 SG_ D2M_IDX_CMD_Type_27 : 0|8@1+ (1,0) [0|255] ""  MBMU
 SG_ D2M_IDX_DCDC_Index_27 : 8|8@1+ (1,0) [0|255] ""  MBMU
 SG_ D2M_DCDC_MatchingCode_27 : 16|8@1+ (1,0) [0|255] ""  MBMU
 SG_ D2M_DCDC_Result_27 : 24|8@1+ (1,0) [0|255] ""  MBMU

BO_ 2467540828 D2M_Index__28: 8 DCDC
 SG_ D2M_IDX_CMD_Type_28 : 0|8@1+ (1,0) [0|255] ""  MBMU
 SG_ D2M_IDX_DCDC_Index_28 : 8|8@1+ (1,0) [0|255] ""  MBMU
 SG_ D2M_DCDC_MatchingCode_28 : 16|8@1+ (1,0) [0|255] ""  MBMU
 SG_ D2M_DCDC_Result_28 : 24|8@1+ (1,0) [0|255] ""  MBMU

BO_ 2467540829 D2M_Index__29: 8 DCDC
 SG_ D2M_IDX_CMD_Type_29 : 0|8@1+ (1,0) [0|255] ""  MBMU
 SG_ D2M_IDX_DCDC_Index_29 : 8|8@1+ (1,0) [0|255] ""  MBMU
 SG_ D2M_DCDC_MatchingCode_29 : 16|8@1+ (1,0) [0|255] ""  MBMU
 SG_ D2M_DCDC_Result_29 : 24|8@1+ (1,0) [0|255] ""  MBMU

BO_ 2467540830 D2M_Index__30: 8 DCDC
 SG_ D2M_IDX_CMD_Type_30 : 0|8@1+ (1,0) [0|255] ""  MBMU
 SG_ D2M_IDX_DCDC_Index_30 : 8|8@1+ (1,0) [0|255] ""  MBMU
 SG_ D2M_DCDC_MatchingCode_30 : 16|8@1+ (1,0) [0|255] ""  MBMU
 SG_ D2M_DCDC_Result_30 : 24|8@1+ (1,0) [0|255] ""  MBMU

BO_ 2467540831 D2M_Index__31: 8 DCDC
 SG_ D2M_IDX_CMD_Type_31 : 0|8@1+ (1,0) [0|255] ""  MBMU
 SG_ D2M_IDX_DCDC_Index_31 : 8|8@1+ (1,0) [0|255] ""  MBMU
 SG_ D2M_DCDC_MatchingCode_31 : 16|8@1+ (1,0) [0|255] ""  MBMU
 SG_ D2M_DCDC_Result_31 : 24|8@1+ (1,0) [0|255] ""  MBMU

BO_ 2467540832 D2M_Index__32: 8 DCDC
 SG_ D2M_IDX_CMD_Type_32 : 0|8@1+ (1,0) [0|255] ""  MBMU
 SG_ D2M_IDX_DCDC_Index_32 : 8|8@1+ (1,0) [0|255] ""  MBMU
 SG_ D2M_DCDC_MatchingCode_32 : 16|8@1+ (1,0) [0|255] ""  MBMU
 SG_ D2M_DCDC_Result_32 : 24|8@1+ (1,0) [0|255] ""  MBMU

BO_ 2467540833 D2M_Index__33: 8 DCDC
 SG_ D2M_IDX_CMD_Type_33 : 0|8@1+ (1,0) [0|255] ""  MBMU
 SG_ D2M_IDX_DCDC_Index_33 : 8|8@1+ (1,0) [0|255] ""  MBMU
 SG_ D2M_DCDC_MatchingCode_33 : 16|8@1+ (1,0) [0|255] ""  MBMU
 SG_ D2M_DCDC_Result_33 : 24|8@1+ (1,0) [0|255] ""  MBMU

BO_ 2467540834 D2M_Index__34: 8 DCDC
 SG_ D2M_IDX_CMD_Type_34 : 0|8@1+ (1,0) [0|255] ""  MBMU
 SG_ D2M_IDX_DCDC_Index_34 : 8|8@1+ (1,0) [0|255] ""  MBMU
 SG_ D2M_DCDC_MatchingCode_34 : 16|8@1+ (1,0) [0|255] ""  MBMU
 SG_ D2M_DCDC_Result_34 : 24|8@1+ (1,0) [0|255] ""  MBMU

BO_ 2467540835 D2M_Index__35: 8 DCDC
 SG_ D2M_IDX_CMD_Type_35 : 0|8@1+ (1,0) [0|255] ""  MBMU
 SG_ D2M_IDX_DCDC_Index_35 : 8|8@1+ (1,0) [0|255] ""  MBMU
 SG_ D2M_DCDC_MatchingCode_35 : 16|8@1+ (1,0) [0|255] ""  MBMU
 SG_ D2M_DCDC_Result_35 : 24|8@1+ (1,0) [0|255] ""  MBMU

BO_ 2467540836 D2M_Index__36: 8 DCDC
 SG_ D2M_IDX_CMD_Type_36 : 0|8@1+ (1,0) [0|255] ""  MBMU
 SG_ D2M_IDX_DCDC_Index_36 : 8|8@1+ (1,0) [0|255] ""  MBMU
 SG_ D2M_DCDC_MatchingCode_36 : 16|8@1+ (1,0) [0|255] ""  MBMU
 SG_ D2M_DCDC_Result_36 : 24|8@1+ (1,0) [0|255] ""  MBMU

BO_ 2467540837 D2M_Index__37: 8 DCDC
 SG_ D2M_IDX_CMD_Type_37 : 0|8@1+ (1,0) [0|255] ""  MBMU
 SG_ D2M_IDX_DCDC_Index_37 : 8|8@1+ (1,0) [0|255] ""  MBMU
 SG_ D2M_DCDC_MatchingCode_37 : 16|8@1+ (1,0) [0|255] ""  MBMU
 SG_ D2M_DCDC_Result_37 : 24|8@1+ (1,0) [0|255] ""  MBMU

BO_ 2467540838 D2M_Index__38: 8 DCDC
 SG_ D2M_IDX_CMD_Type_38 : 0|8@1+ (1,0) [0|255] ""  MBMU
 SG_ D2M_IDX_DCDC_Index_38 : 8|8@1+ (1,0) [0|255] ""  MBMU
 SG_ D2M_DCDC_MatchingCode_38 : 16|8@1+ (1,0) [0|255] ""  MBMU
 SG_ D2M_DCDC_Result_38 : 24|8@1+ (1,0) [0|255] ""  MBMU

BO_ 2467540839 D2M_Index__39: 8 DCDC
 SG_ D2M_IDX_CMD_Type_39 : 0|8@1+ (1,0) [0|255] ""  MBMU
 SG_ D2M_IDX_DCDC_Index_39 : 8|8@1+ (1,0) [0|255] ""  MBMU
 SG_ D2M_DCDC_MatchingCode_39 : 16|8@1+ (1,0) [0|255] ""  MBMU
 SG_ D2M_DCDC_Result_39 : 24|8@1+ (1,0) [0|255] ""  MBMU

BO_ 2467540840 D2M_Index__40: 8 DCDC
 SG_ D2M_IDX_CMD_Type_40 : 0|8@1+ (1,0) [0|255] ""  MBMU
 SG_ D2M_IDX_DCDC_Index_40 : 8|8@1+ (1,0) [0|255] ""  MBMU
 SG_ D2M_DCDC_MatchingCode_40 : 16|8@1+ (1,0) [0|255] ""  MBMU
 SG_ D2M_DCDC_Result_40 : 24|8@1+ (1,0) [0|255] ""  MBMU

BO_ 2467540841 D2M_Index__41: 8 DCDC
 SG_ D2M_IDX_CMD_Type_41 : 0|8@1+ (1,0) [0|255] ""  MBMU
 SG_ D2M_IDX_DCDC_Index_41 : 8|8@1+ (1,0) [0|255] ""  MBMU
 SG_ D2M_DCDC_MatchingCode_41 : 16|8@1+ (1,0) [0|255] ""  MBMU
 SG_ D2M_DCDC_Result_41 : 24|8@1+ (1,0) [0|255] ""  MBMU

BO_ 2467540842 D2M_Index__42: 8 DCDC
 SG_ D2M_IDX_CMD_Type_42 : 0|8@1+ (1,0) [0|255] ""  MBMU
 SG_ D2M_IDX_DCDC_Index_42 : 8|8@1+ (1,0) [0|255] ""  MBMU
 SG_ D2M_DCDC_MatchingCode_42 : 16|8@1+ (1,0) [0|255] ""  MBMU
 SG_ D2M_DCDC_Result_42 : 24|8@1+ (1,0) [0|255] ""  MBMU

BO_ 2467540843 D2M_Index__43: 8 DCDC
 SG_ D2M_IDX_CMD_Type_43 : 0|8@1+ (1,0) [0|255] ""  MBMU
 SG_ D2M_IDX_DCDC_Index_43 : 8|8@1+ (1,0) [0|255] ""  MBMU
 SG_ D2M_DCDC_MatchingCode_43 : 16|8@1+ (1,0) [0|255] ""  MBMU
 SG_ D2M_DCDC_Result_43 : 24|8@1+ (1,0) [0|255] ""  MBMU

BO_ 2467540844 D2M_Index__44: 8 DCDC
 SG_ D2M_IDX_CMD_Type_44 : 0|8@1+ (1,0) [0|255] ""  MBMU
 SG_ D2M_IDX_DCDC_Index_44 : 8|8@1+ (1,0) [0|255] ""  MBMU
 SG_ D2M_DCDC_MatchingCode_44 : 16|8@1+ (1,0) [0|255] ""  MBMU
 SG_ D2M_DCDC_Result_44 : 24|8@1+ (1,0) [0|255] ""  MBMU

BO_ 2467540845 D2M_Index__45: 8 DCDC
 SG_ D2M_IDX_CMD_Type_45 : 0|8@1+ (1,0) [0|255] ""  MBMU
 SG_ D2M_IDX_DCDC_Index_45 : 8|8@1+ (1,0) [0|255] ""  MBMU
 SG_ D2M_DCDC_MatchingCode_45 : 16|8@1+ (1,0) [0|255] ""  MBMU
 SG_ D2M_DCDC_Result_45 : 24|8@1+ (1,0) [0|255] ""  MBMU

BO_ 2467540846 D2M_Index__46: 8 DCDC
 SG_ D2M_IDX_CMD_Type_46 : 0|8@1+ (1,0) [0|255] ""  MBMU
 SG_ D2M_IDX_DCDC_Index_46 : 8|8@1+ (1,0) [0|255] ""  MBMU
 SG_ D2M_DCDC_MatchingCode_46 : 16|8@1+ (1,0) [0|255] ""  MBMU
 SG_ D2M_DCDC_Result_46 : 24|8@1+ (1,0) [0|255] ""  MBMU

BO_ 2467540847 D2M_Index__47: 8 DCDC
 SG_ D2M_IDX_CMD_Type_47 : 0|8@1+ (1,0) [0|255] ""  MBMU
 SG_ D2M_IDX_DCDC_Index_47 : 8|8@1+ (1,0) [0|255] ""  MBMU
 SG_ D2M_DCDC_MatchingCode_47 : 16|8@1+ (1,0) [0|255] ""  MBMU
 SG_ D2M_DCDC_Result_47 : 24|8@1+ (1,0) [0|255] ""  MBMU

BO_ 2467540848 D2M_Index__48: 8 DCDC
 SG_ D2M_IDX_CMD_Type_48 : 0|8@1+ (1,0) [0|255] ""  MBMU
 SG_ D2M_IDX_DCDC_Index_48 : 8|8@1+ (1,0) [0|255] ""  MBMU
 SG_ D2M_DCDC_MatchingCode_48 : 16|8@1+ (1,0) [0|255] ""  MBMU
 SG_ D2M_DCDC_Result_48 : 24|8@1+ (1,0) [0|255] ""  MBMU

BO_ 2467540849 D2M_Index__49: 8 DCDC
 SG_ D2M_IDX_CMD_Type_49 : 0|8@1+ (1,0) [0|255] ""  MBMU
 SG_ D2M_IDX_DCDC_Index_49 : 8|8@1+ (1,0) [0|255] ""  MBMU
 SG_ D2M_DCDC_MatchingCode_49 : 16|8@1+ (1,0) [0|255] ""  MBMU
 SG_ D2M_DCDC_Result_49 : 24|8@1+ (1,0) [0|255] ""  MBMU

BO_ 2467540850 D2M_Index__50: 8 DCDC
 SG_ D2M_IDX_CMD_Type_50 : 0|8@1+ (1,0) [0|255] ""  MBMU
 SG_ D2M_IDX_DCDC_Index_50 : 8|8@1+ (1,0) [0|255] ""  MBMU
 SG_ D2M_DCDC_MatchingCode_50 : 16|8@1+ (1,0) [0|255] ""  MBMU
 SG_ D2M_DCDC_Result_50 : 24|8@1+ (1,0) [0|255] ""  MBMU

BO_ 2467540851 D2M_Index__51: 8 DCDC
 SG_ D2M_IDX_CMD_Type_51 : 0|8@1+ (1,0) [0|255] ""  MBMU
 SG_ D2M_IDX_DCDC_Index_51 : 8|8@1+ (1,0) [0|255] ""  MBMU
 SG_ D2M_DCDC_MatchingCode_51 : 16|8@1+ (1,0) [0|255] ""  MBMU
 SG_ D2M_DCDC_Result_51 : 24|8@1+ (1,0) [0|255] ""  MBMU

BO_ 2467540852 D2M_Index__52: 8 DCDC
 SG_ D2M_IDX_CMD_Type_52 : 0|8@1+ (1,0) [0|255] ""  MBMU
 SG_ D2M_IDX_DCDC_Index_52 : 8|8@1+ (1,0) [0|255] ""  MBMU
 SG_ D2M_DCDC_MatchingCode_52 : 16|8@1+ (1,0) [0|255] ""  MBMU
 SG_ D2M_DCDC_Result_52 : 24|8@1+ (1,0) [0|255] ""  MBMU

BO_ 2467540853 D2M_Index__53: 8 DCDC
 SG_ D2M_IDX_CMD_Type_53 : 0|8@1+ (1,0) [0|255] ""  MBMU
 SG_ D2M_IDX_DCDC_Index_53 : 8|8@1+ (1,0) [0|255] ""  MBMU
 SG_ D2M_DCDC_MatchingCode_53 : 16|8@1+ (1,0) [0|255] ""  MBMU
 SG_ D2M_DCDC_Result_53 : 24|8@1+ (1,0) [0|255] ""  MBMU

BO_ 2467540854 D2M_Index__54: 8 DCDC
 SG_ D2M_IDX_CMD_Type_54 : 0|8@1+ (1,0) [0|255] ""  MBMU
 SG_ D2M_IDX_DCDC_Index_54 : 8|8@1+ (1,0) [0|255] ""  MBMU
 SG_ D2M_DCDC_MatchingCode_54 : 16|8@1+ (1,0) [0|255] ""  MBMU
 SG_ D2M_DCDC_Result_54 : 24|8@1+ (1,0) [0|255] ""  MBMU

BO_ 2467540855 D2M_Index__55: 8 DCDC
 SG_ D2M_IDX_CMD_Type_55 : 0|8@1+ (1,0) [0|255] ""  MBMU
 SG_ D2M_IDX_DCDC_Index_55 : 8|8@1+ (1,0) [0|255] ""  MBMU
 SG_ D2M_DCDC_MatchingCode_55 : 16|8@1+ (1,0) [0|255] ""  MBMU
 SG_ D2M_DCDC_Result_55 : 24|8@1+ (1,0) [0|255] ""  MBMU

BO_ 2467540856 D2M_Index__56: 8 DCDC
 SG_ D2M_IDX_CMD_Type_56 : 0|8@1+ (1,0) [0|255] ""  MBMU
 SG_ D2M_IDX_DCDC_Index_56 : 8|8@1+ (1,0) [0|255] ""  MBMU
 SG_ D2M_DCDC_MatchingCode_56 : 16|8@1+ (1,0) [0|255] ""  MBMU
 SG_ D2M_DCDC_Result_56 : 24|8@1+ (1,0) [0|255] ""  MBMU

BO_ 2467540857 D2M_Index__57: 8 DCDC
 SG_ D2M_IDX_CMD_Type_57 : 0|8@1+ (1,0) [0|255] ""  MBMU
 SG_ D2M_IDX_DCDC_Index_57 : 8|8@1+ (1,0) [0|255] ""  MBMU
 SG_ D2M_DCDC_MatchingCode_57 : 16|8@1+ (1,0) [0|255] ""  MBMU
 SG_ D2M_DCDC_Result_57 : 24|8@1+ (1,0) [0|255] ""  MBMU

BO_ 2467540858 D2M_Index__58: 8 DCDC
 SG_ D2M_IDX_CMD_Type_58 : 0|8@1+ (1,0) [0|255] ""  MBMU
 SG_ D2M_IDX_DCDC_Index_58 : 8|8@1+ (1,0) [0|255] ""  MBMU
 SG_ D2M_DCDC_MatchingCode_58 : 16|8@1+ (1,0) [0|255] ""  MBMU
 SG_ D2M_DCDC_Result_58 : 24|8@1+ (1,0) [0|255] ""  MBMU

BO_ 2467540859 D2M_Index__59: 8 DCDC
 SG_ D2M_IDX_CMD_Type_59 : 0|8@1+ (1,0) [0|255] ""  MBMU
 SG_ D2M_IDX_DCDC_Index_59 : 8|8@1+ (1,0) [0|255] ""  MBMU
 SG_ D2M_DCDC_MatchingCode_59 : 16|8@1+ (1,0) [0|255] ""  MBMU
 SG_ D2M_DCDC_Result_59 : 24|8@1+ (1,0) [0|255] ""  MBMU

BO_ 2467540860 D2M_Index__60: 8 DCDC
 SG_ D2M_IDX_CMD_Type_60 : 0|8@1+ (1,0) [0|255] ""  MBMU
 SG_ D2M_IDX_DCDC_Index_60 : 8|8@1+ (1,0) [0|255] ""  MBMU
 SG_ D2M_DCDC_MatchingCode_60 : 16|8@1+ (1,0) [0|255] ""  MBMU
 SG_ D2M_DCDC_Result_60 : 24|8@1+ (1,0) [0|255] ""  MBMU

BO_ 2467540861 D2M_Index__61: 8 DCDC
 SG_ D2M_IDX_CMD_Type_61 : 0|8@1+ (1,0) [0|255] ""  MBMU
 SG_ D2M_IDX_DCDC_Index_61 : 8|8@1+ (1,0) [0|255] ""  MBMU
 SG_ D2M_DCDC_MatchingCode_61 : 16|8@1+ (1,0) [0|255] ""  MBMU
 SG_ D2M_DCDC_Result_61 : 24|8@1+ (1,0) [0|255] ""  MBMU

BO_ 2467540862 D2M_Index__62: 8 DCDC
 SG_ D2M_IDX_CMD_Type_62 : 0|8@1+ (1,0) [0|255] ""  MBMU
 SG_ D2M_IDX_DCDC_Index_62 : 8|8@1+ (1,0) [0|255] ""  MBMU
 SG_ D2M_DCDC_MatchingCode_62 : 16|8@1+ (1,0) [0|255] ""  MBMU
 SG_ D2M_DCDC_Result_62 : 24|8@1+ (1,0) [0|255] ""  MBMU

BO_ 2467540863 D2M_Index__63: 8 DCDC
 SG_ D2M_IDX_CMD_Type_63 : 0|8@1+ (1,0) [0|255] ""  MBMU
 SG_ D2M_IDX_DCDC_Index_63 : 8|8@1+ (1,0) [0|255] ""  MBMU
 SG_ D2M_DCDC_MatchingCode_63 : 16|8@1+ (1,0) [0|255] ""  MBMU
 SG_ D2M_DCDC_Result_63 : 24|8@1+ (1,0) [0|255] ""  MBMU

BO_ 2333278017 S2A_SUMDATA12__01: 8 SBMU
 SG_ S2A_HIS_ChgCapAh_01 : 0|32@1+ (0.1,0) [0|429496729.5] "Ah"  MBMU
 SG_ S2A_HIS_DisChgCapAh_01 : 32|32@1+ (0.1,0) [0|429496729.5] "Ah"  MBMU

BO_ 2333278018 S2A_SUMDATA12__02: 8 SBMU
 SG_ S2A_HIS_ChgCapAh_02 : 0|32@1+ (0.1,0) [0|429496729.5] "Ah"  MBMU
 SG_ S2A_HIS_DisChgCapAh_02 : 32|32@1+ (0.1,0) [0|429496729.5] "Ah"  MBMU

BO_ 2333278019 S2A_SUMDATA12__03: 8 SBMU
 SG_ S2A_HIS_ChgCapAh_03 : 0|32@1+ (0.1,0) [0|429496729.5] "Ah"  MBMU
 SG_ S2A_HIS_DisChgCapAh_03 : 32|32@1+ (0.1,0) [0|429496729.5] "Ah"  MBMU

BO_ 2333278020 S2A_SUMDATA12__04: 8 SBMU
 SG_ S2A_HIS_ChgCapAh_04 : 0|32@1+ (0.1,0) [0|429496729.5] "Ah"  MBMU
 SG_ S2A_HIS_DisChgCapAh_04 : 32|32@1+ (0.1,0) [0|429496729.5] "Ah"  MBMU

BO_ 2333278021 S2A_SUMDATA12__05: 8 SBMU
 SG_ S2A_HIS_ChgCapAh_05 : 0|32@1+ (0.1,0) [0|429496729.5] "Ah"  MBMU
 SG_ S2A_HIS_DisChgCapAh_05 : 32|32@1+ (0.1,0) [0|429496729.5] "Ah"  MBMU

BO_ 2333278022 S2A_SUMDATA12__06: 8 SBMU
 SG_ S2A_HIS_ChgCapAh_06 : 0|32@1+ (0.1,0) [0|429496729.5] "Ah"  MBMU
 SG_ S2A_HIS_DisChgCapAh_06 : 32|32@1+ (0.1,0) [0|429496729.5] "Ah"  MBMU

BO_ 2333278023 S2A_SUMDATA12__07: 8 SBMU
 SG_ S2A_HIS_ChgCapAh_07 : 0|32@1+ (0.1,0) [0|429496729.5] "Ah"  MBMU
 SG_ S2A_HIS_DisChgCapAh_07 : 32|32@1+ (0.1,0) [0|429496729.5] "Ah"  MBMU

BO_ 2333278024 S2A_SUMDATA12__08: 8 SBMU
 SG_ S2A_HIS_ChgCapAh_08 : 0|32@1+ (0.1,0) [0|429496729.5] "Ah"  MBMU
 SG_ S2A_HIS_DisChgCapAh_08 : 32|32@1+ (0.1,0) [0|429496729.5] "Ah"  MBMU

BO_ 2333278025 S2A_SUMDATA12__09: 8 SBMU
 SG_ S2A_HIS_ChgCapAh_09 : 0|32@1+ (0.1,0) [0|429496729.5] "Ah"  MBMU
 SG_ S2A_HIS_DisChgCapAh_09 : 32|32@1+ (0.1,0) [0|429496729.5] "Ah"  MBMU

BO_ 2333278026 S2A_SUMDATA12__10: 8 SBMU
 SG_ S2A_HIS_ChgCapAh_10 : 0|32@1+ (0.1,0) [0|429496729.5] "Ah"  MBMU
 SG_ S2A_HIS_DisChgCapAh_10 : 32|32@1+ (0.1,0) [0|429496729.5] "Ah"  MBMU

BO_ 2333278027 S2A_SUMDATA12__11: 8 SBMU
 SG_ S2A_HIS_ChgCapAh_11 : 0|32@1+ (0.1,0) [0|429496729.5] "Ah"  MBMU
 SG_ S2A_HIS_DisChgCapAh_11 : 32|32@1+ (0.1,0) [0|429496729.5] "Ah"  MBMU

BO_ 2333278028 S2A_SUMDATA12__12: 8 SBMU
 SG_ S2A_HIS_ChgCapAh_12 : 0|32@1+ (0.1,0) [0|429496729.5] "Ah"  MBMU
 SG_ S2A_HIS_DisChgCapAh_12 : 32|32@1+ (0.1,0) [0|429496729.5] "Ah"  MBMU

BO_ 2333278029 S2A_SUMDATA12__13: 8 SBMU
 SG_ S2A_HIS_ChgCapAh_13 : 0|32@1+ (0.1,0) [0|429496729.5] "Ah"  MBMU
 SG_ S2A_HIS_DisChgCapAh_13 : 32|32@1+ (0.1,0) [0|429496729.5] "Ah"  MBMU

BO_ 2333278030 S2A_SUMDATA12__14: 8 SBMU
 SG_ S2A_HIS_ChgCapAh_14 : 0|32@1+ (0.1,0) [0|429496729.5] "Ah"  MBMU
 SG_ S2A_HIS_DisChgCapAh_14 : 32|32@1+ (0.1,0) [0|429496729.5] "Ah"  MBMU

BO_ 2333278031 S2A_SUMDATA12__15: 8 SBMU
 SG_ S2A_HIS_ChgCapAh_15 : 0|32@1+ (0.1,0) [0|429496729.5] "Ah"  MBMU
 SG_ S2A_HIS_DisChgCapAh_15 : 32|32@1+ (0.1,0) [0|429496729.5] "Ah"  MBMU

BO_ 2333278032 S2A_SUMDATA12__16: 8 SBMU
 SG_ S2A_HIS_ChgCapAh_16 : 0|32@1+ (0.1,0) [0|429496729.5] "Ah"  MBMU
 SG_ S2A_HIS_DisChgCapAh_16 : 32|32@1+ (0.1,0) [0|429496729.5] "Ah"  MBMU

BO_ 2333278033 S2A_SUMDATA12__17: 8 SBMU
 SG_ S2A_HIS_ChgCapAh_17 : 0|32@1+ (0.1,0) [0|429496729.5] "Ah"  MBMU
 SG_ S2A_HIS_DisChgCapAh_17 : 32|32@1+ (0.1,0) [0|429496729.5] "Ah"  MBMU

BO_ 2333278034 S2A_SUMDATA12__18: 8 SBMU
 SG_ S2A_HIS_ChgCapAh_18 : 0|32@1+ (0.1,0) [0|429496729.5] "Ah"  MBMU
 SG_ S2A_HIS_DisChgCapAh_18 : 32|32@1+ (0.1,0) [0|429496729.5] "Ah"  MBMU

BO_ 2333278035 S2A_SUMDATA12__19: 8 SBMU
 SG_ S2A_HIS_ChgCapAh_19 : 0|32@1+ (0.1,0) [0|429496729.5] "Ah"  MBMU
 SG_ S2A_HIS_DisChgCapAh_19 : 32|32@1+ (0.1,0) [0|429496729.5] "Ah"  MBMU

BO_ 2333278036 S2A_SUMDATA12__20: 8 SBMU
 SG_ S2A_HIS_ChgCapAh_20 : 0|32@1+ (0.1,0) [0|429496729.5] "Ah"  MBMU
 SG_ S2A_HIS_DisChgCapAh_20 : 32|32@1+ (0.1,0) [0|429496729.5] "Ah"  MBMU

BO_ 2333278037 S2A_SUMDATA12__21: 8 SBMU
 SG_ S2A_HIS_ChgCapAh_21 : 0|32@1+ (0.1,0) [0|429496729.5] "Ah"  MBMU
 SG_ S2A_HIS_DisChgCapAh_21 : 32|32@1+ (0.1,0) [0|429496729.5] "Ah"  MBMU

BO_ 2333278038 S2A_SUMDATA12__22: 8 SBMU
 SG_ S2A_HIS_ChgCapAh_22 : 0|32@1+ (0.1,0) [0|429496729.5] "Ah"  MBMU
 SG_ S2A_HIS_DisChgCapAh_22 : 32|32@1+ (0.1,0) [0|429496729.5] "Ah"  MBMU

BO_ 2333278039 S2A_SUMDATA12__23: 8 SBMU
 SG_ S2A_HIS_ChgCapAh_23 : 0|32@1+ (0.1,0) [0|429496729.5] "Ah"  MBMU
 SG_ S2A_HIS_DisChgCapAh_23 : 32|32@1+ (0.1,0) [0|429496729.5] "Ah"  MBMU

BO_ 2333278040 S2A_SUMDATA12__24: 8 SBMU
 SG_ S2A_HIS_ChgCapAh_24 : 0|32@1+ (0.1,0) [0|429496729.5] "Ah"  MBMU
 SG_ S2A_HIS_DisChgCapAh_24 : 32|32@1+ (0.1,0) [0|429496729.5] "Ah"  MBMU

BO_ 2333278041 S2A_SUMDATA12__25: 8 SBMU
 SG_ S2A_HIS_ChgCapAh_25 : 0|32@1+ (0.1,0) [0|429496729.5] "Ah"  MBMU
 SG_ S2A_HIS_DisChgCapAh_25 : 32|32@1+ (0.1,0) [0|429496729.5] "Ah"  MBMU

BO_ 2333278042 S2A_SUMDATA12__26: 8 SBMU
 SG_ S2A_HIS_ChgCapAh_26 : 0|32@1+ (0.1,0) [0|429496729.5] "Ah"  MBMU
 SG_ S2A_HIS_DisChgCapAh_26 : 32|32@1+ (0.1,0) [0|429496729.5] "Ah"  MBMU

BO_ 2333278043 S2A_SUMDATA12__27: 8 SBMU
 SG_ S2A_HIS_ChgCapAh_27 : 0|32@1+ (0.1,0) [0|429496729.5] "Ah"  MBMU
 SG_ S2A_HIS_DisChgCapAh_27 : 32|32@1+ (0.1,0) [0|429496729.5] "Ah"  MBMU

BO_ 2333278044 S2A_SUMDATA12__28: 8 SBMU
 SG_ S2A_HIS_ChgCapAh_28 : 0|32@1+ (0.1,0) [0|429496729.5] "Ah"  MBMU
 SG_ S2A_HIS_DisChgCapAh_28 : 32|32@1+ (0.1,0) [0|429496729.5] "Ah"  MBMU

BO_ 2333278045 S2A_SUMDATA12__29: 8 SBMU
 SG_ S2A_HIS_ChgCapAh_29 : 0|32@1+ (0.1,0) [0|429496729.5] "Ah"  MBMU
 SG_ S2A_HIS_DisChgCapAh_29 : 32|32@1+ (0.1,0) [0|429496729.5] "Ah"  MBMU

BO_ 2333278046 S2A_SUMDATA12__30: 8 SBMU
 SG_ S2A_HIS_ChgCapAh_30 : 0|32@1+ (0.1,0) [0|429496729.5] "Ah"  MBMU
 SG_ S2A_HIS_DisChgCapAh_30 : 32|32@1+ (0.1,0) [0|429496729.5] "Ah"  MBMU

BO_ 2333278047 S2A_SUMDATA12__31: 8 SBMU
 SG_ S2A_HIS_ChgCapAh_31 : 0|32@1+ (0.1,0) [0|429496729.5] "Ah"  MBMU
 SG_ S2A_HIS_DisChgCapAh_31 : 32|32@1+ (0.1,0) [0|429496729.5] "Ah"  MBMU

BO_ 2333278048 S2A_SUMDATA12__32: 8 SBMU
 SG_ S2A_HIS_ChgCapAh_32 : 0|32@1+ (0.1,0) [0|429496729.5] "Ah"  MBMU
 SG_ S2A_HIS_DisChgCapAh_32 : 32|32@1+ (0.1,0) [0|429496729.5] "Ah"  MBMU

BO_ 2333278049 S2A_SUMDATA12__33: 8 SBMU
 SG_ S2A_HIS_ChgCapAh_33 : 0|32@1+ (0.1,0) [0|429496729.5] "Ah"  MBMU
 SG_ S2A_HIS_DisChgCapAh_33 : 32|32@1+ (0.1,0) [0|429496729.5] "Ah"  MBMU

BO_ 2333278050 S2A_SUMDATA12__34: 8 SBMU
 SG_ S2A_HIS_ChgCapAh_34 : 0|32@1+ (0.1,0) [0|429496729.5] "Ah"  MBMU
 SG_ S2A_HIS_DisChgCapAh_34 : 32|32@1+ (0.1,0) [0|429496729.5] "Ah"  MBMU

BO_ 2333278051 S2A_SUMDATA12__35: 8 SBMU
 SG_ S2A_HIS_ChgCapAh_35 : 0|32@1+ (0.1,0) [0|429496729.5] "Ah"  MBMU
 SG_ S2A_HIS_DisChgCapAh_35 : 32|32@1+ (0.1,0) [0|429496729.5] "Ah"  MBMU

BO_ 2333278052 S2A_SUMDATA12__36: 8 SBMU
 SG_ S2A_HIS_ChgCapAh_36 : 0|32@1+ (0.1,0) [0|429496729.5] "Ah"  MBMU
 SG_ S2A_HIS_DisChgCapAh_36 : 32|32@1+ (0.1,0) [0|429496729.5] "Ah"  MBMU

BO_ 2333278053 S2A_SUMDATA12__37: 8 SBMU
 SG_ S2A_HIS_ChgCapAh_37 : 0|32@1+ (0.1,0) [0|429496729.5] "Ah"  MBMU
 SG_ S2A_HIS_DisChgCapAh_37 : 32|32@1+ (0.1,0) [0|429496729.5] "Ah"  MBMU

BO_ 2333278054 S2A_SUMDATA12__38: 8 SBMU
 SG_ S2A_HIS_ChgCapAh_38 : 0|32@1+ (0.1,0) [0|429496729.5] "Ah"  MBMU
 SG_ S2A_HIS_DisChgCapAh_38 : 32|32@1+ (0.1,0) [0|429496729.5] "Ah"  MBMU

BO_ 2333278055 S2A_SUMDATA12__39: 8 SBMU
 SG_ S2A_HIS_ChgCapAh_39 : 0|32@1+ (0.1,0) [0|429496729.5] "Ah"  MBMU
 SG_ S2A_HIS_DisChgCapAh_39 : 32|32@1+ (0.1,0) [0|429496729.5] "Ah"  MBMU

BO_ 2333278056 S2A_SUMDATA12__40: 8 SBMU
 SG_ S2A_HIS_ChgCapAh_40 : 0|32@1+ (0.1,0) [0|429496729.5] "Ah"  MBMU
 SG_ S2A_HIS_DisChgCapAh_40 : 32|32@1+ (0.1,0) [0|429496729.5] "Ah"  MBMU

BO_ 2333278057 S2A_SUMDATA12__41: 8 SBMU
 SG_ S2A_HIS_ChgCapAh_41 : 0|32@1+ (0.1,0) [0|429496729.5] "Ah"  MBMU
 SG_ S2A_HIS_DisChgCapAh_41 : 32|32@1+ (0.1,0) [0|429496729.5] "Ah"  MBMU

BO_ 2333278058 S2A_SUMDATA12__42: 8 SBMU
 SG_ S2A_HIS_ChgCapAh_42 : 0|32@1+ (0.1,0) [0|429496729.5] "Ah"  MBMU
 SG_ S2A_HIS_DisChgCapAh_42 : 32|32@1+ (0.1,0) [0|429496729.5] "Ah"  MBMU

BO_ 2333278059 S2A_SUMDATA12__43: 8 SBMU
 SG_ S2A_HIS_ChgCapAh_43 : 0|32@1+ (0.1,0) [0|429496729.5] "Ah"  MBMU
 SG_ S2A_HIS_DisChgCapAh_43 : 32|32@1+ (0.1,0) [0|429496729.5] "Ah"  MBMU

BO_ 2333278060 S2A_SUMDATA12__44: 8 SBMU
 SG_ S2A_HIS_ChgCapAh_44 : 0|32@1+ (0.1,0) [0|429496729.5] "Ah"  MBMU
 SG_ S2A_HIS_DisChgCapAh_44 : 32|32@1+ (0.1,0) [0|429496729.5] "Ah"  MBMU

BO_ 2333278061 S2A_SUMDATA12__45: 8 SBMU
 SG_ S2A_HIS_ChgCapAh_45 : 0|32@1+ (0.1,0) [0|429496729.5] "Ah"  MBMU
 SG_ S2A_HIS_DisChgCapAh_45 : 32|32@1+ (0.1,0) [0|429496729.5] "Ah"  MBMU

BO_ 2333278062 S2A_SUMDATA12__46: 8 SBMU
 SG_ S2A_HIS_ChgCapAh_46 : 0|32@1+ (0.1,0) [0|429496729.5] "Ah"  MBMU
 SG_ S2A_HIS_DisChgCapAh_46 : 32|32@1+ (0.1,0) [0|429496729.5] "Ah"  MBMU

BO_ 2333278063 S2A_SUMDATA12__47: 8 SBMU
 SG_ S2A_HIS_ChgCapAh_47 : 0|32@1+ (0.1,0) [0|429496729.5] "Ah"  MBMU
 SG_ S2A_HIS_DisChgCapAh_47 : 32|32@1+ (0.1,0) [0|429496729.5] "Ah"  MBMU

BO_ 2333278064 S2A_SUMDATA12__48: 8 SBMU
 SG_ S2A_HIS_ChgCapAh_48 : 0|32@1+ (0.1,0) [0|429496729.5] "Ah"  MBMU
 SG_ S2A_HIS_DisChgCapAh_48 : 32|32@1+ (0.1,0) [0|429496729.5] "Ah"  MBMU

BO_ 2333278065 S2A_SUMDATA12__49: 8 SBMU
 SG_ S2A_HIS_ChgCapAh_49 : 0|32@1+ (0.1,0) [0|429496729.5] "Ah"  MBMU
 SG_ S2A_HIS_DisChgCapAh_49 : 32|32@1+ (0.1,0) [0|429496729.5] "Ah"  MBMU

BO_ 2333278066 S2A_SUMDATA12__50: 8 SBMU
 SG_ S2A_HIS_ChgCapAh_50 : 0|32@1+ (0.1,0) [0|429496729.5] "Ah"  MBMU
 SG_ S2A_HIS_DisChgCapAh_50 : 32|32@1+ (0.1,0) [0|429496729.5] "Ah"  MBMU

BO_ 2333278067 S2A_SUMDATA12__51: 8 SBMU
 SG_ S2A_HIS_ChgCapAh_51 : 0|32@1+ (0.1,0) [0|429496729.5] "Ah"  MBMU
 SG_ S2A_HIS_DisChgCapAh_51 : 32|32@1+ (0.1,0) [0|429496729.5] "Ah"  MBMU

BO_ 2333278068 S2A_SUMDATA12__52: 8 SBMU
 SG_ S2A_HIS_ChgCapAh_52 : 0|32@1+ (0.1,0) [0|429496729.5] "Ah"  MBMU
 SG_ S2A_HIS_DisChgCapAh_52 : 32|32@1+ (0.1,0) [0|429496729.5] "Ah"  MBMU

BO_ 2333278069 S2A_SUMDATA12__53: 8 SBMU
 SG_ S2A_HIS_ChgCapAh_53 : 0|32@1+ (0.1,0) [0|429496729.5] "Ah"  MBMU
 SG_ S2A_HIS_DisChgCapAh_53 : 32|32@1+ (0.1,0) [0|429496729.5] "Ah"  MBMU

BO_ 2333278070 S2A_SUMDATA12__54: 8 SBMU
 SG_ S2A_HIS_ChgCapAh_54 : 0|32@1+ (0.1,0) [0|429496729.5] "Ah"  MBMU
 SG_ S2A_HIS_DisChgCapAh_54 : 32|32@1+ (0.1,0) [0|429496729.5] "Ah"  MBMU

BO_ 2333278071 S2A_SUMDATA12__55: 8 SBMU
 SG_ S2A_HIS_ChgCapAh_55 : 0|32@1+ (0.1,0) [0|429496729.5] "Ah"  MBMU
 SG_ S2A_HIS_DisChgCapAh_55 : 32|32@1+ (0.1,0) [0|429496729.5] "Ah"  MBMU

BO_ 2333278072 S2A_SUMDATA12__56: 8 SBMU
 SG_ S2A_HIS_ChgCapAh_56 : 0|32@1+ (0.1,0) [0|429496729.5] "Ah"  MBMU
 SG_ S2A_HIS_DisChgCapAh_56 : 32|32@1+ (0.1,0) [0|429496729.5] "Ah"  MBMU

BO_ 2333278073 S2A_SUMDATA12__57: 8 SBMU
 SG_ S2A_HIS_ChgCapAh_57 : 0|32@1+ (0.1,0) [0|429496729.5] "Ah"  MBMU
 SG_ S2A_HIS_DisChgCapAh_57 : 32|32@1+ (0.1,0) [0|429496729.5] "Ah"  MBMU

BO_ 2333278074 S2A_SUMDATA12__58: 8 SBMU
 SG_ S2A_HIS_ChgCapAh_58 : 0|32@1+ (0.1,0) [0|429496729.5] "Ah"  MBMU
 SG_ S2A_HIS_DisChgCapAh_58 : 32|32@1+ (0.1,0) [0|429496729.5] "Ah"  MBMU

BO_ 2333278075 S2A_SUMDATA12__59: 8 SBMU
 SG_ S2A_HIS_ChgCapAh_59 : 0|32@1+ (0.1,0) [0|429496729.5] "Ah"  MBMU
 SG_ S2A_HIS_DisChgCapAh_59 : 32|32@1+ (0.1,0) [0|429496729.5] "Ah"  MBMU

BO_ 2333278076 S2A_SUMDATA12__60: 8 SBMU
 SG_ S2A_HIS_ChgCapAh_60 : 0|32@1+ (0.1,0) [0|429496729.5] "Ah"  MBMU
 SG_ S2A_HIS_DisChgCapAh_60 : 32|32@1+ (0.1,0) [0|429496729.5] "Ah"  MBMU

BO_ 2333278077 S2A_SUMDATA12__61: 8 SBMU
 SG_ S2A_HIS_ChgCapAh_61 : 0|32@1+ (0.1,0) [0|429496729.5] "Ah"  MBMU
 SG_ S2A_HIS_DisChgCapAh_61 : 32|32@1+ (0.1,0) [0|429496729.5] "Ah"  MBMU

BO_ 2333278078 S2A_SUMDATA12__62: 8 SBMU
 SG_ S2A_HIS_ChgCapAh_62 : 0|32@1+ (0.1,0) [0|429496729.5] "Ah"  MBMU
 SG_ S2A_HIS_DisChgCapAh_62 : 32|32@1+ (0.1,0) [0|429496729.5] "Ah"  MBMU

BO_ 2333278079 S2A_SUMDATA12__63: 8 SBMU
 SG_ S2A_HIS_ChgCapAh_63 : 0|32@1+ (0.1,0) [0|429496729.5] "Ah"  MBMU
 SG_ S2A_HIS_DisChgCapAh_63 : 32|32@1+ (0.1,0) [0|429496729.5] "Ah"  MBMU

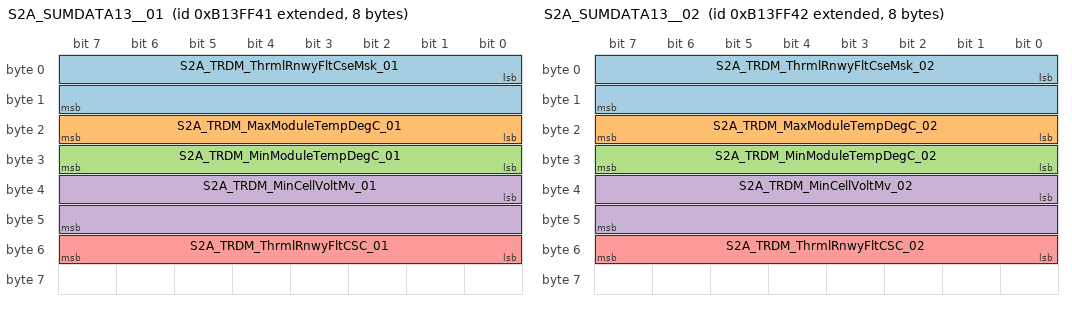
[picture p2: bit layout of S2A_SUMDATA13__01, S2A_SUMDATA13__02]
BO_ 2333343553 S2A_SUMDATA13__01: 8 SBMU
 SG_ S2A_TRDM_ThrmlRnwyFltCseMsk_01 : 0|16@1+ (1,0) [0|65535] ""  MBMU,PC
 SG_ S2A_TRDM_MaxModuleTempDegC_01 : 16|8@1+ (1,0) [0|255] ""  MBMU,PC
 SG_ S2A_TRDM_MinModuleTempDegC_01 : 24|8@1+ (1,0) [0|255] ""  MBMU,PC
 SG_ S2A_TRDM_MinCellVoltMv_01 : 32|16@1+ (1,0) [0|65535] ""  MBMU,PC
 SG_ S2A_TRDM_ThrmlRnwyFltCSC_01 : 48|8@1+ (1,0) [0|255] ""  MBMU,PC

BO_ 2333343554 S2A_SUMDATA13__02: 8 SBMU
 SG_ S2A_TRDM_ThrmlRnwyFltCseMsk_02 : 0|16@1+ (1,0) [0|65535] ""  MBMU,PC
 SG_ S2A_TRDM_MaxModuleTempDegC_02 : 16|8@1+ (1,0) [0|255] ""  MBMU,PC
 SG_ S2A_TRDM_MinModuleTempDegC_02 : 24|8@1+ (1,0) [0|255] ""  MBMU,PC
 SG_ S2A_TRDM_MinCellVoltMv_02 : 32|16@1+ (1,0) [0|65535] ""  MBMU,PC
 SG_ S2A_TRDM_ThrmlRnwyFltCSC_02 : 48|8@1+ (1,0) [0|255] ""  MBMU,PC

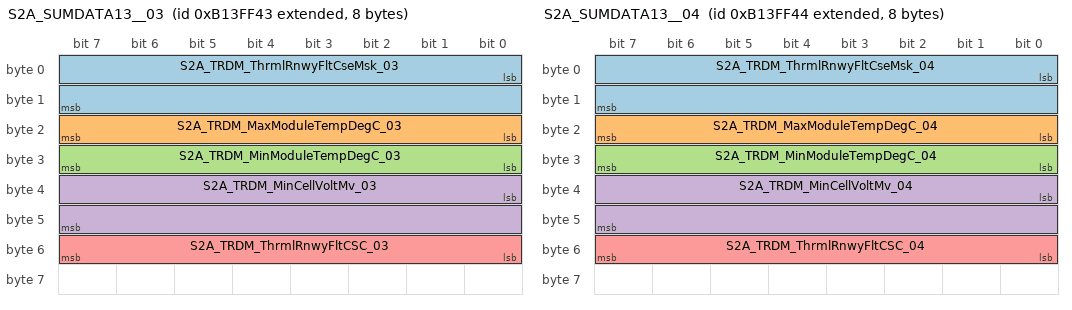
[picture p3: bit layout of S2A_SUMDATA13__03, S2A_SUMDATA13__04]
BO_ 2333343555 S2A_SUMDATA13__03: 8 SBMU
 SG_ S2A_TRDM_ThrmlRnwyFltCseMsk_03 : 0|16@1+ (1,0) [0|65535] ""  MBMU,PC
 SG_ S2A_TRDM_MaxModuleTempDegC_03 : 16|8@1+ (1,0) [0|255] ""  MBMU,PC
 SG_ S2A_TRDM_MinModuleTempDegC_03 : 24|8@1+ (1,0) [0|255] ""  MBMU,PC
 SG_ S2A_TRDM_MinCellVoltMv_03 : 32|16@1+ (1,0) [0|65535] ""  MBMU,PC
 SG_ S2A_TRDM_ThrmlRnwyFltCSC_03 : 48|8@1+ (1,0) [0|255] ""  MBMU,PC

BO_ 2333343556 S2A_SUMDATA13__04: 8 SBMU
 SG_ S2A_TRDM_ThrmlRnwyFltCseMsk_04 : 0|16@1+ (1,0) [0|65535] ""  MBMU,PC
 SG_ S2A_TRDM_MaxModuleTempDegC_04 : 16|8@1+ (1,0) [0|255] ""  MBMU,PC
 SG_ S2A_TRDM_MinModuleTempDegC_04 : 24|8@1+ (1,0) [0|255] ""  MBMU,PC
 SG_ S2A_TRDM_MinCellVoltMv_04 : 32|16@1+ (1,0) [0|65535] ""  MBMU,PC
 SG_ S2A_TRDM_ThrmlRnwyFltCSC_04 : 48|8@1+ (1,0) [0|255] ""  MBMU,PC

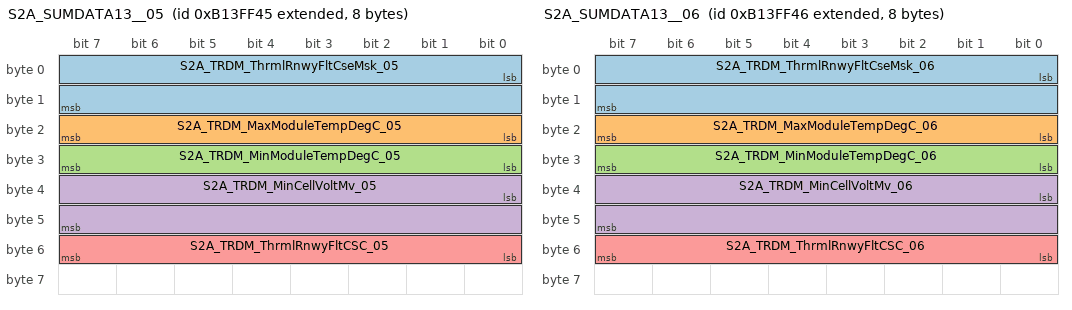
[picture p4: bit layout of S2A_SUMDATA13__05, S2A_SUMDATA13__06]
BO_ 2333343557 S2A_SUMDATA13__05: 8 SBMU
 SG_ S2A_TRDM_ThrmlRnwyFltCseMsk_05 : 0|16@1+ (1,0) [0|65535] ""  MBMU,PC
 SG_ S2A_TRDM_MaxModuleTempDegC_05 : 16|8@1+ (1,0) [0|255] ""  MBMU,PC
 SG_ S2A_TRDM_MinModuleTempDegC_05 : 24|8@1+ (1,0) [0|255] ""  MBMU,PC
 SG_ S2A_TRDM_MinCellVoltMv_05 : 32|16@1+ (1,0) [0|65535] ""  MBMU,PC
 SG_ S2A_TRDM_ThrmlRnwyFltCSC_05 : 48|8@1+ (1,0) [0|255] ""  MBMU,PC

BO_ 2333343558 S2A_SUMDATA13__06: 8 SBMU
 SG_ S2A_TRDM_ThrmlRnwyFltCseMsk_06 : 0|16@1+ (1,0) [0|65535] ""  MBMU,PC
 SG_ S2A_TRDM_MaxModuleTempDegC_06 : 16|8@1+ (1,0) [0|255] ""  MBMU,PC
 SG_ S2A_TRDM_MinModuleTempDegC_06 : 24|8@1+ (1,0) [0|255] ""  MBMU,PC
 SG_ S2A_TRDM_MinCellVoltMv_06 : 32|16@1+ (1,0) [0|65535] ""  MBMU,PC
 SG_ S2A_TRDM_ThrmlRnwyFltCSC_06 : 48|8@1+ (1,0) [0|255] ""  MBMU,PC

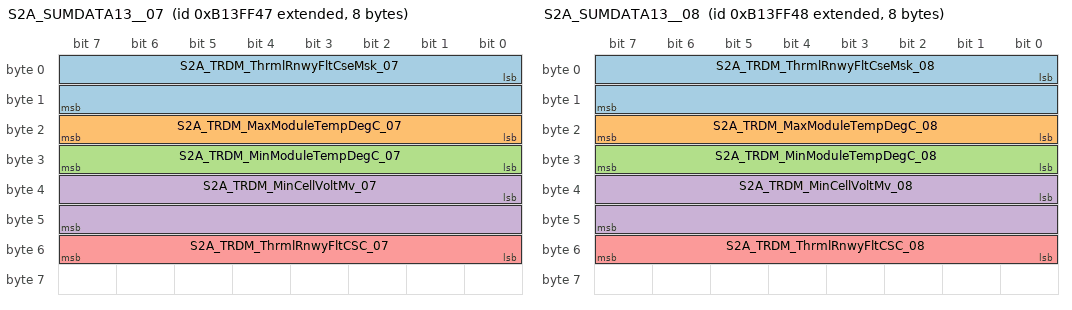
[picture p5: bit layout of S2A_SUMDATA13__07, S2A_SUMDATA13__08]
BO_ 2333343559 S2A_SUMDATA13__07: 8 SBMU
 SG_ S2A_TRDM_ThrmlRnwyFltCseMsk_07 : 0|16@1+ (1,0) [0|65535] ""  MBMU,PC
 SG_ S2A_TRDM_MaxModuleTempDegC_07 : 16|8@1+ (1,0) [0|255] ""  MBMU,PC
 SG_ S2A_TRDM_MinModuleTempDegC_07 : 24|8@1+ (1,0) [0|255] ""  MBMU,PC
 SG_ S2A_TRDM_MinCellVoltMv_07 : 32|16@1+ (1,0) [0|65535] ""  MBMU,PC
 SG_ S2A_TRDM_ThrmlRnwyFltCSC_07 : 48|8@1+ (1,0) [0|255] ""  MBMU,PC

BO_ 2333343560 S2A_SUMDATA13__08: 8 SBMU
 SG_ S2A_TRDM_ThrmlRnwyFltCseMsk_08 : 0|16@1+ (1,0) [0|65535] ""  MBMU,PC
 SG_ S2A_TRDM_MaxModuleTempDegC_08 : 16|8@1+ (1,0) [0|255] ""  MBMU,PC
 SG_ S2A_TRDM_MinModuleTempDegC_08 : 24|8@1+ (1,0) [0|255] ""  MBMU,PC
 SG_ S2A_TRDM_MinCellVoltMv_08 : 32|16@1+ (1,0) [0|65535] ""  MBMU,PC
 SG_ S2A_TRDM_ThrmlRnwyFltCSC_08 : 48|8@1+ (1,0) [0|255] ""  MBMU,PC

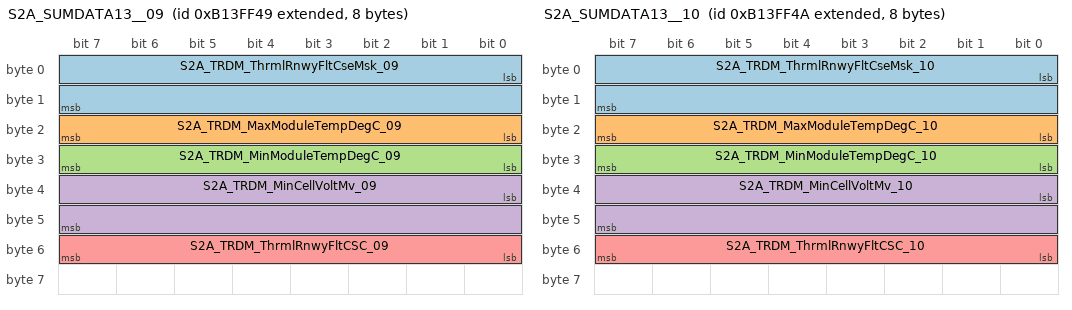
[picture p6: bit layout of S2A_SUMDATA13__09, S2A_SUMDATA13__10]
BO_ 2333343561 S2A_SUMDATA13__09: 8 SBMU
 SG_ S2A_TRDM_ThrmlRnwyFltCseMsk_09 : 0|16@1+ (1,0) [0|65535] ""  MBMU,PC
 SG_ S2A_TRDM_MaxModuleTempDegC_09 : 16|8@1+ (1,0) [0|255] ""  MBMU,PC
 SG_ S2A_TRDM_MinModuleTempDegC_09 : 24|8@1+ (1,0) [0|255] ""  MBMU,PC
 SG_ S2A_TRDM_MinCellVoltMv_09 : 32|16@1+ (1,0) [0|65535] ""  MBMU,PC
 SG_ S2A_TRDM_ThrmlRnwyFltCSC_09 : 48|8@1+ (1,0) [0|255] ""  MBMU,PC

BO_ 2333343562 S2A_SUMDATA13__10: 8 SBMU
 SG_ S2A_TRDM_ThrmlRnwyFltCseMsk_10 : 0|16@1+ (1,0) [0|65535] ""  MBMU,PC
 SG_ S2A_TRDM_MaxModuleTempDegC_10 : 16|8@1+ (1,0) [0|255] ""  MBMU,PC
 SG_ S2A_TRDM_MinModuleTempDegC_10 : 24|8@1+ (1,0) [0|255] ""  MBMU,PC
 SG_ S2A_TRDM_MinCellVoltMv_10 : 32|16@1+ (1,0) [0|65535] ""  MBMU,PC
 SG_ S2A_TRDM_ThrmlRnwyFltCSC_10 : 48|8@1+ (1,0) [0|255] ""  MBMU,PC

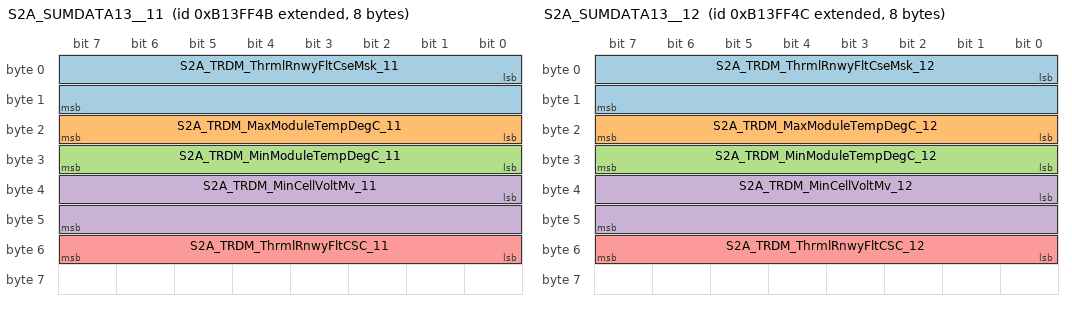
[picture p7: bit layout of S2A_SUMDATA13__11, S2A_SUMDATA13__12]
BO_ 2333343563 S2A_SUMDATA13__11: 8 SBMU
 SG_ S2A_TRDM_ThrmlRnwyFltCseMsk_11 : 0|16@1+ (1,0) [0|65535] ""  MBMU,PC
 SG_ S2A_TRDM_MaxModuleTempDegC_11 : 16|8@1+ (1,0) [0|255] ""  MBMU,PC
 SG_ S2A_TRDM_MinModuleTempDegC_11 : 24|8@1+ (1,0) [0|255] ""  MBMU,PC
 SG_ S2A_TRDM_MinCellVoltMv_11 : 32|16@1+ (1,0) [0|65535] ""  MBMU,PC
 SG_ S2A_TRDM_ThrmlRnwyFltCSC_11 : 48|8@1+ (1,0) [0|255] ""  MBMU,PC

BO_ 2333343564 S2A_SUMDATA13__12: 8 SBMU
 SG_ S2A_TRDM_ThrmlRnwyFltCseMsk_12 : 0|16@1+ (1,0) [0|65535] ""  MBMU,PC
 SG_ S2A_TRDM_MaxModuleTempDegC_12 : 16|8@1+ (1,0) [0|255] ""  MBMU,PC
 SG_ S2A_TRDM_MinModuleTempDegC_12 : 24|8@1+ (1,0) [0|255] ""  MBMU,PC
 SG_ S2A_TRDM_MinCellVoltMv_12 : 32|16@1+ (1,0) [0|65535] ""  MBMU,PC
 SG_ S2A_TRDM_ThrmlRnwyFltCSC_12 : 48|8@1+ (1,0) [0|255] ""  MBMU,PC

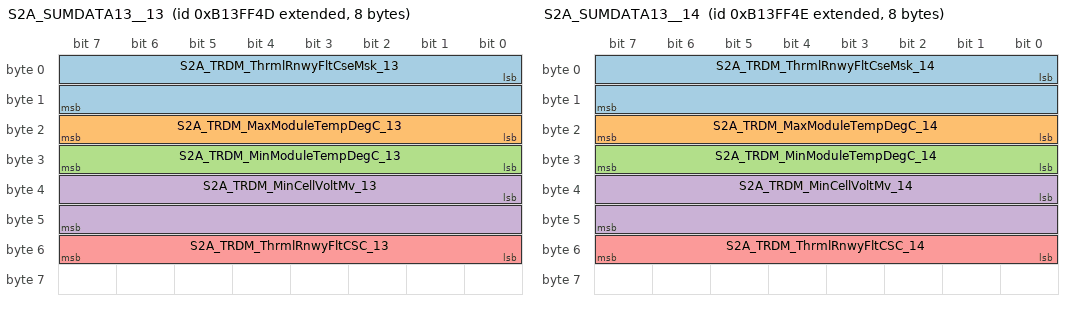
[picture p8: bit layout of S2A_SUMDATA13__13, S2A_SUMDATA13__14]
BO_ 2333343565 S2A_SUMDATA13__13: 8 SBMU
 SG_ S2A_TRDM_ThrmlRnwyFltCseMsk_13 : 0|16@1+ (1,0) [0|65535] ""  MBMU,PC
 SG_ S2A_TRDM_MaxModuleTempDegC_13 : 16|8@1+ (1,0) [0|255] ""  MBMU,PC
 SG_ S2A_TRDM_MinModuleTempDegC_13 : 24|8@1+ (1,0) [0|255] ""  MBMU,PC
 SG_ S2A_TRDM_MinCellVoltMv_13 : 32|16@1+ (1,0) [0|65535] ""  MBMU,PC
 SG_ S2A_TRDM_ThrmlRnwyFltCSC_13 : 48|8@1+ (1,0) [0|255] ""  MBMU,PC

BO_ 2333343566 S2A_SUMDATA13__14: 8 SBMU
 SG_ S2A_TRDM_ThrmlRnwyFltCseMsk_14 : 0|16@1+ (1,0) [0|65535] ""  MBMU,PC
 SG_ S2A_TRDM_MaxModuleTempDegC_14 : 16|8@1+ (1,0) [0|255] ""  MBMU,PC
 SG_ S2A_TRDM_MinModuleTempDegC_14 : 24|8@1+ (1,0) [0|255] ""  MBMU,PC
 SG_ S2A_TRDM_MinCellVoltMv_14 : 32|16@1+ (1,0) [0|65535] ""  MBMU,PC
 SG_ S2A_TRDM_ThrmlRnwyFltCSC_14 : 48|8@1+ (1,0) [0|255] ""  MBMU,PC

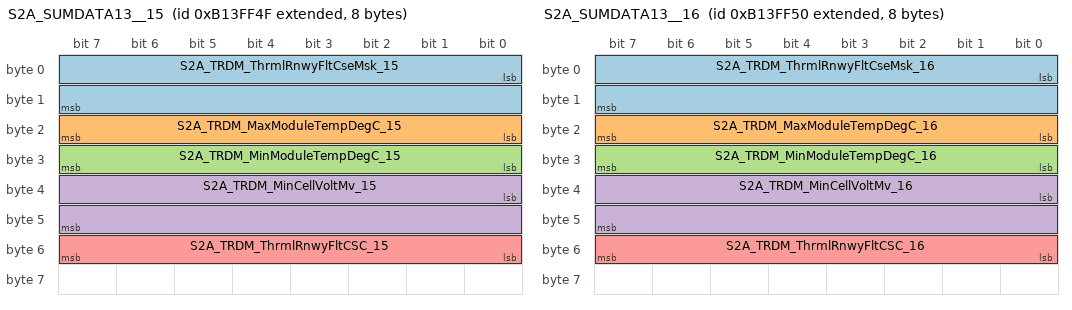
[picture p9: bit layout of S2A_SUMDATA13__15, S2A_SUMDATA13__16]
BO_ 2333343567 S2A_SUMDATA13__15: 8 SBMU
 SG_ S2A_TRDM_ThrmlRnwyFltCseMsk_15 : 0|16@1+ (1,0) [0|65535] ""  MBMU,PC
 SG_ S2A_TRDM_MaxModuleTempDegC_15 : 16|8@1+ (1,0) [0|255] ""  MBMU,PC
 SG_ S2A_TRDM_MinModuleTempDegC_15 : 24|8@1+ (1,0) [0|255] ""  MBMU,PC
 SG_ S2A_TRDM_MinCellVoltMv_15 : 32|16@1+ (1,0) [0|65535] ""  MBMU,PC
 SG_ S2A_TRDM_ThrmlRnwyFltCSC_15 : 48|8@1+ (1,0) [0|255] ""  MBMU,PC

BO_ 2333343568 S2A_SUMDATA13__16: 8 SBMU
 SG_ S2A_TRDM_ThrmlRnwyFltCseMsk_16 : 0|16@1+ (1,0) [0|65535] ""  MBMU,PC
 SG_ S2A_TRDM_MaxModuleTempDegC_16 : 16|8@1+ (1,0) [0|255] ""  MBMU,PC
 SG_ S2A_TRDM_MinModuleTempDegC_16 : 24|8@1+ (1,0) [0|255] ""  MBMU,PC
 SG_ S2A_TRDM_MinCellVoltMv_16 : 32|16@1+ (1,0) [0|65535] ""  MBMU,PC
 SG_ S2A_TRDM_ThrmlRnwyFltCSC_16 : 48|8@1+ (1,0) [0|255] ""  MBMU,PC

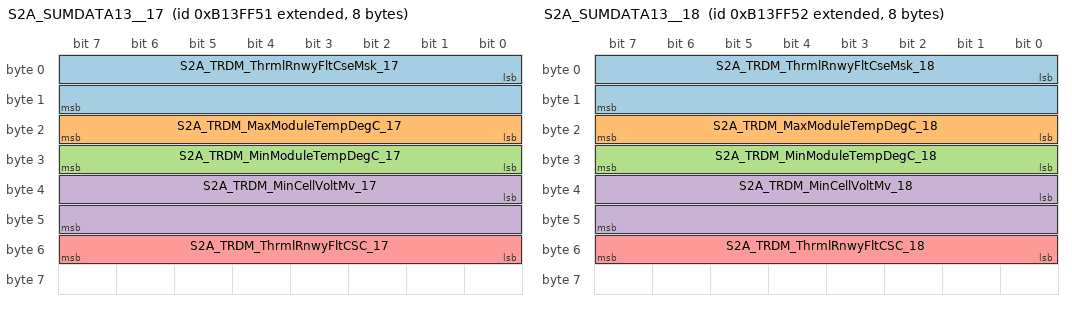
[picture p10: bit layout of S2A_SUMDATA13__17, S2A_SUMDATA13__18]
BO_ 2333343569 S2A_SUMDATA13__17: 8 SBMU
 SG_ S2A_TRDM_ThrmlRnwyFltCseMsk_17 : 0|16@1+ (1,0) [0|65535] ""  MBMU,PC
 SG_ S2A_TRDM_MaxModuleTempDegC_17 : 16|8@1+ (1,0) [0|255] ""  MBMU,PC
 SG_ S2A_TRDM_MinModuleTempDegC_17 : 24|8@1+ (1,0) [0|255] ""  MBMU,PC
 SG_ S2A_TRDM_MinCellVoltMv_17 : 32|16@1+ (1,0) [0|65535] ""  MBMU,PC
 SG_ S2A_TRDM_ThrmlRnwyFltCSC_17 : 48|8@1+ (1,0) [0|255] ""  MBMU,PC

BO_ 2333343570 S2A_SUMDATA13__18: 8 SBMU
 SG_ S2A_TRDM_ThrmlRnwyFltCseMsk_18 : 0|16@1+ (1,0) [0|65535] ""  MBMU,PC
 SG_ S2A_TRDM_MaxModuleTempDegC_18 : 16|8@1+ (1,0) [0|255] ""  MBMU,PC
 SG_ S2A_TRDM_MinModuleTempDegC_18 : 24|8@1+ (1,0) [0|255] ""  MBMU,PC
 SG_ S2A_TRDM_MinCellVoltMv_18 : 32|16@1+ (1,0) [0|65535] ""  MBMU,PC
 SG_ S2A_TRDM_ThrmlRnwyFltCSC_18 : 48|8@1+ (1,0) [0|255] ""  MBMU,PC

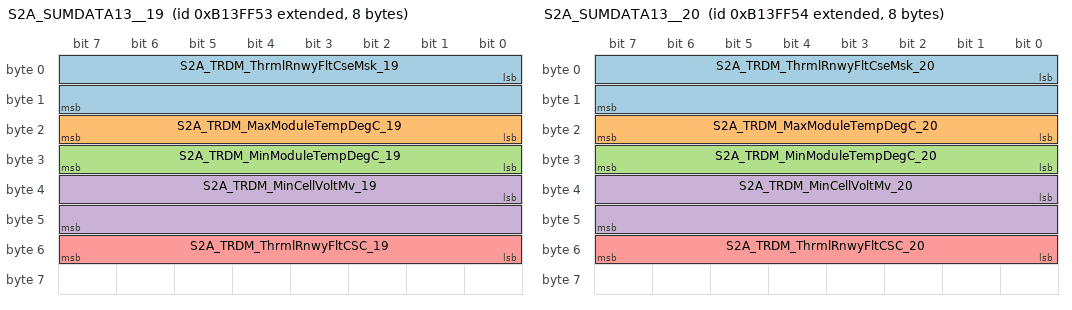
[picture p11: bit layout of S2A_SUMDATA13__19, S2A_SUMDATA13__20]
BO_ 2333343571 S2A_SUMDATA13__19: 8 SBMU
 SG_ S2A_TRDM_ThrmlRnwyFltCseMsk_19 : 0|16@1+ (1,0) [0|65535] ""  MBMU,PC
 SG_ S2A_TRDM_MaxModuleTempDegC_19 : 16|8@1+ (1,0) [0|255] ""  MBMU,PC
 SG_ S2A_TRDM_MinModuleTempDegC_19 : 24|8@1+ (1,0) [0|255] ""  MBMU,PC
 SG_ S2A_TRDM_MinCellVoltMv_19 : 32|16@1+ (1,0) [0|65535] ""  MBMU,PC
 SG_ S2A_TRDM_ThrmlRnwyFltCSC_19 : 48|8@1+ (1,0) [0|255] ""  MBMU,PC

BO_ 2333343572 S2A_SUMDATA13__20: 8 SBMU
 SG_ S2A_TRDM_ThrmlRnwyFltCseMsk_20 : 0|16@1+ (1,0) [0|65535] ""  MBMU,PC
 SG_ S2A_TRDM_MaxModuleTempDegC_20 : 16|8@1+ (1,0) [0|255] ""  MBMU,PC
 SG_ S2A_TRDM_MinModuleTempDegC_20 : 24|8@1+ (1,0) [0|255] ""  MBMU,PC
 SG_ S2A_TRDM_MinCellVoltMv_20 : 32|16@1+ (1,0) [0|65535] ""  MBMU,PC
 SG_ S2A_TRDM_ThrmlRnwyFltCSC_20 : 48|8@1+ (1,0) [0|255] ""  MBMU,PC

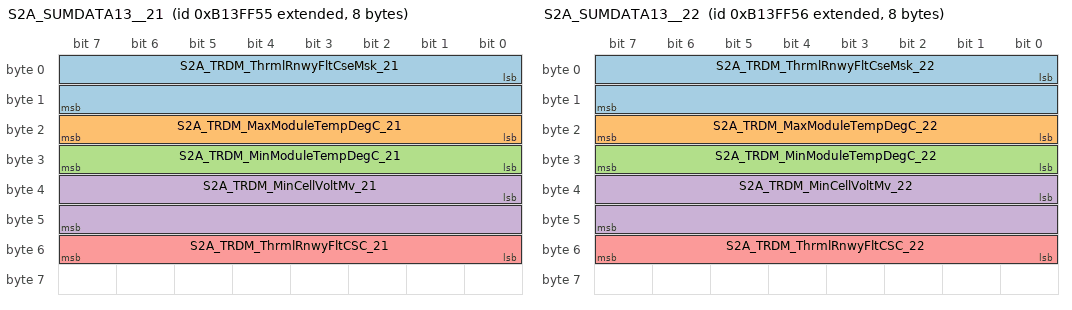
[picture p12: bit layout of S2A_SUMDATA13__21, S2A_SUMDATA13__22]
BO_ 2333343573 S2A_SUMDATA13__21: 8 SBMU
 SG_ S2A_TRDM_ThrmlRnwyFltCseMsk_21 : 0|16@1+ (1,0) [0|65535] ""  MBMU,PC
 SG_ S2A_TRDM_MaxModuleTempDegC_21 : 16|8@1+ (1,0) [0|255] ""  MBMU,PC
 SG_ S2A_TRDM_MinModuleTempDegC_21 : 24|8@1+ (1,0) [0|255] ""  MBMU,PC
 SG_ S2A_TRDM_MinCellVoltMv_21 : 32|16@1+ (1,0) [0|65535] ""  MBMU,PC
 SG_ S2A_TRDM_ThrmlRnwyFltCSC_21 : 48|8@1+ (1,0) [0|255] ""  MBMU,PC

BO_ 2333343574 S2A_SUMDATA13__22: 8 SBMU
 SG_ S2A_TRDM_ThrmlRnwyFltCseMsk_22 : 0|16@1+ (1,0) [0|65535] ""  MBMU,PC
 SG_ S2A_TRDM_MaxModuleTempDegC_22 : 16|8@1+ (1,0) [0|255] ""  MBMU,PC
 SG_ S2A_TRDM_MinModuleTempDegC_22 : 24|8@1+ (1,0) [0|255] ""  MBMU,PC
 SG_ S2A_TRDM_MinCellVoltMv_22 : 32|16@1+ (1,0) [0|65535] ""  MBMU,PC
 SG_ S2A_TRDM_ThrmlRnwyFltCSC_22 : 48|8@1+ (1,0) [0|255] ""  MBMU,PC

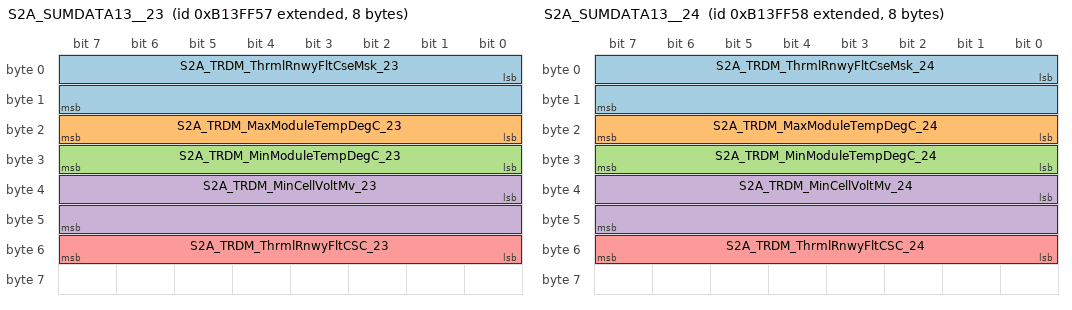
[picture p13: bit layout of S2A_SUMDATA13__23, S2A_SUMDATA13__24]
BO_ 2333343575 S2A_SUMDATA13__23: 8 SBMU
 SG_ S2A_TRDM_ThrmlRnwyFltCseMsk_23 : 0|16@1+ (1,0) [0|65535] ""  MBMU,PC
 SG_ S2A_TRDM_MaxModuleTempDegC_23 : 16|8@1+ (1,0) [0|255] ""  MBMU,PC
 SG_ S2A_TRDM_MinModuleTempDegC_23 : 24|8@1+ (1,0) [0|255] ""  MBMU,PC
 SG_ S2A_TRDM_MinCellVoltMv_23 : 32|16@1+ (1,0) [0|65535] ""  MBMU,PC
 SG_ S2A_TRDM_ThrmlRnwyFltCSC_23 : 48|8@1+ (1,0) [0|255] ""  MBMU,PC

BO_ 2333343576 S2A_SUMDATA13__24: 8 SBMU
 SG_ S2A_TRDM_ThrmlRnwyFltCseMsk_24 : 0|16@1+ (1,0) [0|65535] ""  MBMU,PC
 SG_ S2A_TRDM_MaxModuleTempDegC_24 : 16|8@1+ (1,0) [0|255] ""  MBMU,PC
 SG_ S2A_TRDM_MinModuleTempDegC_24 : 24|8@1+ (1,0) [0|255] ""  MBMU,PC
 SG_ S2A_TRDM_MinCellVoltMv_24 : 32|16@1+ (1,0) [0|65535] ""  MBMU,PC
 SG_ S2A_TRDM_ThrmlRnwyFltCSC_24 : 48|8@1+ (1,0) [0|255] ""  MBMU,PC

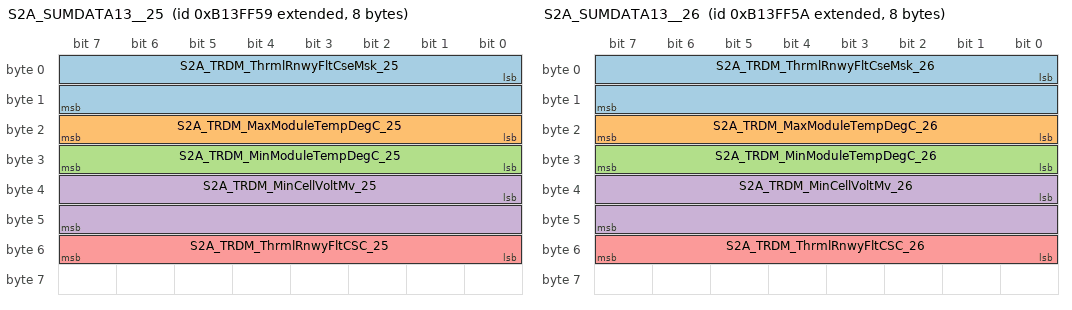
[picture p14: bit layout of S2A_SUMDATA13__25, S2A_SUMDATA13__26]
BO_ 2333343577 S2A_SUMDATA13__25: 8 SBMU
 SG_ S2A_TRDM_ThrmlRnwyFltCseMsk_25 : 0|16@1+ (1,0) [0|65535] ""  MBMU,PC
 SG_ S2A_TRDM_MaxModuleTempDegC_25 : 16|8@1+ (1,0) [0|255] ""  MBMU,PC
 SG_ S2A_TRDM_MinModuleTempDegC_25 : 24|8@1+ (1,0) [0|255] ""  MBMU,PC
 SG_ S2A_TRDM_MinCellVoltMv_25 : 32|16@1+ (1,0) [0|65535] ""  MBMU,PC
 SG_ S2A_TRDM_ThrmlRnwyFltCSC_25 : 48|8@1+ (1,0) [0|255] ""  MBMU,PC

BO_ 2333343578 S2A_SUMDATA13__26: 8 SBMU
 SG_ S2A_TRDM_ThrmlRnwyFltCseMsk_26 : 0|16@1+ (1,0) [0|65535] ""  MBMU,PC
 SG_ S2A_TRDM_MaxModuleTempDegC_26 : 16|8@1+ (1,0) [0|255] ""  MBMU,PC
 SG_ S2A_TRDM_MinModuleTempDegC_26 : 24|8@1+ (1,0) [0|255] ""  MBMU,PC
 SG_ S2A_TRDM_MinCellVoltMv_26 : 32|16@1+ (1,0) [0|65535] ""  MBMU,PC
 SG_ S2A_TRDM_ThrmlRnwyFltCSC_26 : 48|8@1+ (1,0) [0|255] ""  MBMU,PC

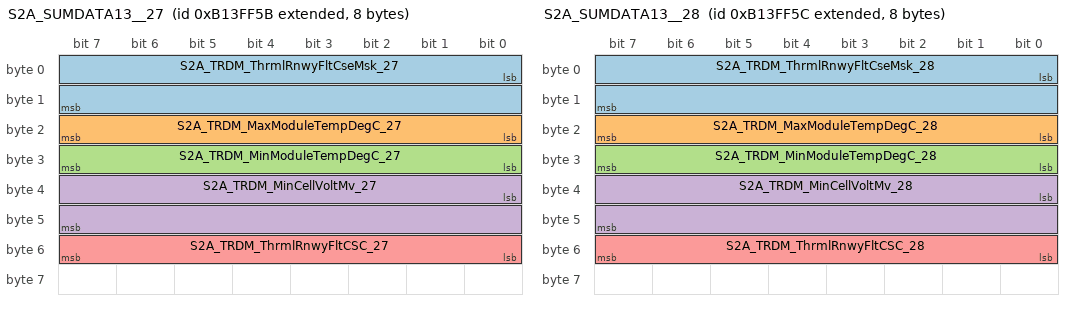
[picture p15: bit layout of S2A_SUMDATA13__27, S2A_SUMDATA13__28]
BO_ 2333343579 S2A_SUMDATA13__27: 8 SBMU
 SG_ S2A_TRDM_ThrmlRnwyFltCseMsk_27 : 0|16@1+ (1,0) [0|65535] ""  MBMU,PC
 SG_ S2A_TRDM_MaxModuleTempDegC_27 : 16|8@1+ (1,0) [0|255] ""  MBMU,PC
 SG_ S2A_TRDM_MinModuleTempDegC_27 : 24|8@1+ (1,0) [0|255] ""  MBMU,PC
 SG_ S2A_TRDM_MinCellVoltMv_27 : 32|16@1+ (1,0) [0|65535] ""  MBMU,PC
 SG_ S2A_TRDM_ThrmlRnwyFltCSC_27 : 48|8@1+ (1,0) [0|255] ""  MBMU,PC

BO_ 2333343580 S2A_SUMDATA13__28: 8 SBMU
 SG_ S2A_TRDM_ThrmlRnwyFltCseMsk_28 : 0|16@1+ (1,0) [0|65535] ""  MBMU,PC
 SG_ S2A_TRDM_MaxModuleTempDegC_28 : 16|8@1+ (1,0) [0|255] ""  MBMU,PC
 SG_ S2A_TRDM_MinModuleTempDegC_28 : 24|8@1+ (1,0) [0|255] ""  MBMU,PC
 SG_ S2A_TRDM_MinCellVoltMv_28 : 32|16@1+ (1,0) [0|65535] ""  MBMU,PC
 SG_ S2A_TRDM_ThrmlRnwyFltCSC_28 : 48|8@1+ (1,0) [0|255] ""  MBMU,PC

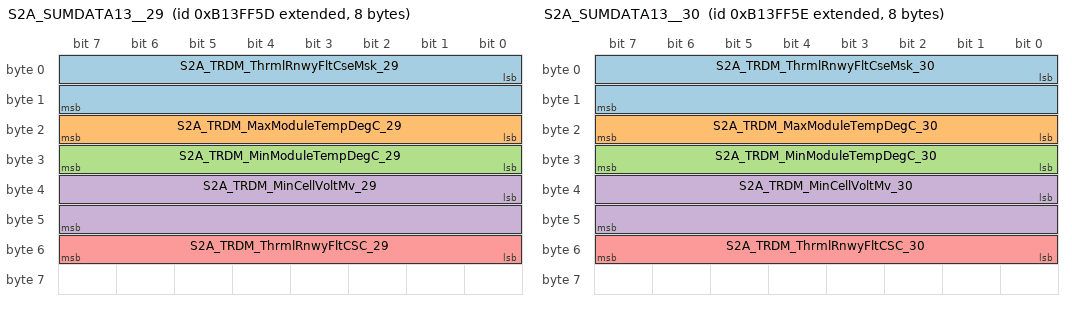
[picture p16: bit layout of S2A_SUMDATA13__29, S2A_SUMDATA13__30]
BO_ 2333343581 S2A_SUMDATA13__29: 8 SBMU
 SG_ S2A_TRDM_ThrmlRnwyFltCseMsk_29 : 0|16@1+ (1,0) [0|65535] ""  MBMU,PC
 SG_ S2A_TRDM_MaxModuleTempDegC_29 : 16|8@1+ (1,0) [0|255] ""  MBMU,PC
 SG_ S2A_TRDM_MinModuleTempDegC_29 : 24|8@1+ (1,0) [0|255] ""  MBMU,PC
 SG_ S2A_TRDM_MinCellVoltMv_29 : 32|16@1+ (1,0) [0|65535] ""  MBMU,PC
 SG_ S2A_TRDM_ThrmlRnwyFltCSC_29 : 48|8@1+ (1,0) [0|255] ""  MBMU,PC

BO_ 2333343582 S2A_SUMDATA13__30: 8 SBMU
 SG_ S2A_TRDM_ThrmlRnwyFltCseMsk_30 : 0|16@1+ (1,0) [0|65535] ""  MBMU,PC
 SG_ S2A_TRDM_MaxModuleTempDegC_30 : 16|8@1+ (1,0) [0|255] ""  MBMU,PC
 SG_ S2A_TRDM_MinModuleTempDegC_30 : 24|8@1+ (1,0) [0|255] ""  MBMU,PC
 SG_ S2A_TRDM_MinCellVoltMv_30 : 32|16@1+ (1,0) [0|65535] ""  MBMU,PC
 SG_ S2A_TRDM_ThrmlRnwyFltCSC_30 : 48|8@1+ (1,0) [0|255] ""  MBMU,PC

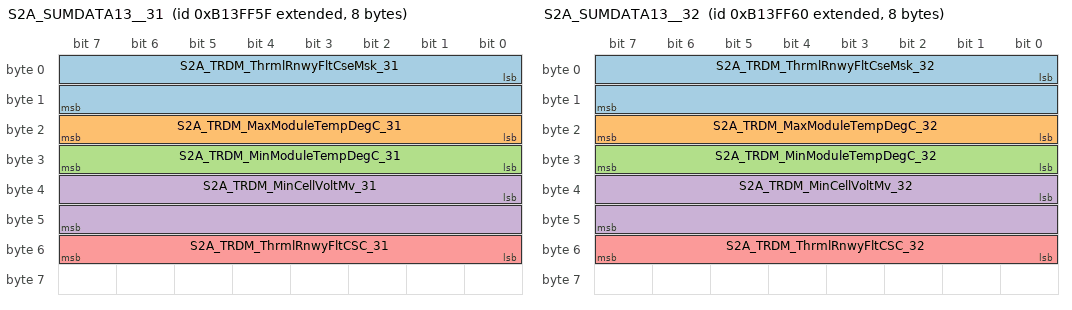
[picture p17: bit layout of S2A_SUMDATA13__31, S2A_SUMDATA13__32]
BO_ 2333343583 S2A_SUMDATA13__31: 8 SBMU
 SG_ S2A_TRDM_ThrmlRnwyFltCseMsk_31 : 0|16@1+ (1,0) [0|65535] ""  MBMU,PC
 SG_ S2A_TRDM_MaxModuleTempDegC_31 : 16|8@1+ (1,0) [0|255] ""  MBMU,PC
 SG_ S2A_TRDM_MinModuleTempDegC_31 : 24|8@1+ (1,0) [0|255] ""  MBMU,PC
 SG_ S2A_TRDM_MinCellVoltMv_31 : 32|16@1+ (1,0) [0|65535] ""  MBMU,PC
 SG_ S2A_TRDM_ThrmlRnwyFltCSC_31 : 48|8@1+ (1,0) [0|255] ""  MBMU,PC

BO_ 2333343584 S2A_SUMDATA13__32: 8 SBMU
 SG_ S2A_TRDM_ThrmlRnwyFltCseMsk_32 : 0|16@1+ (1,0) [0|65535] ""  MBMU,PC
 SG_ S2A_TRDM_MaxModuleTempDegC_32 : 16|8@1+ (1,0) [0|255] ""  MBMU,PC
 SG_ S2A_TRDM_MinModuleTempDegC_32 : 24|8@1+ (1,0) [0|255] ""  MBMU,PC
 SG_ S2A_TRDM_MinCellVoltMv_32 : 32|16@1+ (1,0) [0|65535] ""  MBMU,PC
 SG_ S2A_TRDM_ThrmlRnwyFltCSC_32 : 48|8@1+ (1,0) [0|255] ""  MBMU,PC

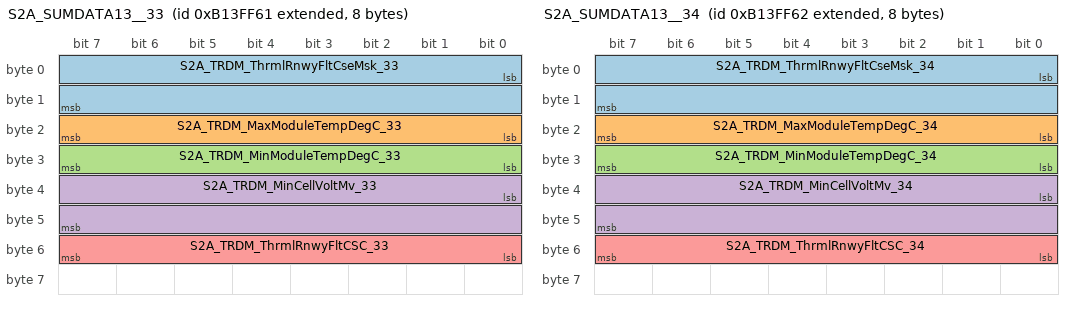
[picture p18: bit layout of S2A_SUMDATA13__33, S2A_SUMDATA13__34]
BO_ 2333343585 S2A_SUMDATA13__33: 8 SBMU
 SG_ S2A_TRDM_ThrmlRnwyFltCseMsk_33 : 0|16@1+ (1,0) [0|65535] ""  MBMU,PC
 SG_ S2A_TRDM_MaxModuleTempDegC_33 : 16|8@1+ (1,0) [0|255] ""  MBMU,PC
 SG_ S2A_TRDM_MinModuleTempDegC_33 : 24|8@1+ (1,0) [0|255] ""  MBMU,PC
 SG_ S2A_TRDM_MinCellVoltMv_33 : 32|16@1+ (1,0) [0|65535] ""  MBMU,PC
 SG_ S2A_TRDM_ThrmlRnwyFltCSC_33 : 48|8@1+ (1,0) [0|255] ""  MBMU,PC

BO_ 2333343586 S2A_SUMDATA13__34: 8 SBMU
 SG_ S2A_TRDM_ThrmlRnwyFltCseMsk_34 : 0|16@1+ (1,0) [0|65535] ""  MBMU,PC
 SG_ S2A_TRDM_MaxModuleTempDegC_34 : 16|8@1+ (1,0) [0|255] ""  MBMU,PC
 SG_ S2A_TRDM_MinModuleTempDegC_34 : 24|8@1+ (1,0) [0|255] ""  MBMU,PC
 SG_ S2A_TRDM_MinCellVoltMv_34 : 32|16@1+ (1,0) [0|65535] ""  MBMU,PC
 SG_ S2A_TRDM_ThrmlRnwyFltCSC_34 : 48|8@1+ (1,0) [0|255] ""  MBMU,PC

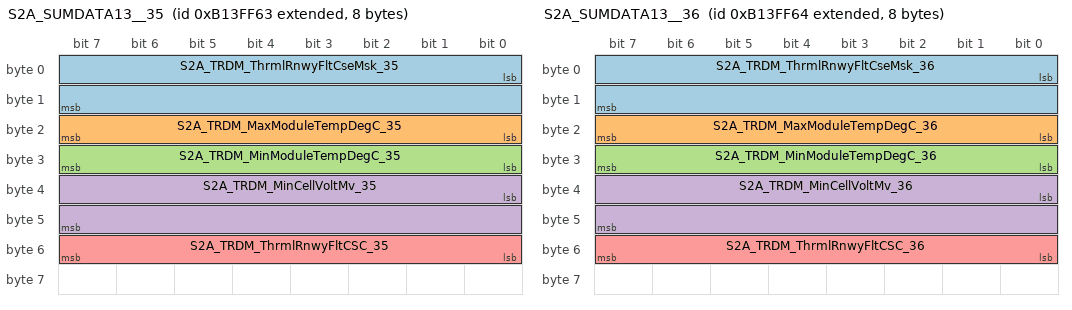
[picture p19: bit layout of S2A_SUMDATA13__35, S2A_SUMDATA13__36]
BO_ 2333343587 S2A_SUMDATA13__35: 8 SBMU
 SG_ S2A_TRDM_ThrmlRnwyFltCseMsk_35 : 0|16@1+ (1,0) [0|65535] ""  MBMU,PC
 SG_ S2A_TRDM_MaxModuleTempDegC_35 : 16|8@1+ (1,0) [0|255] ""  MBMU,PC
 SG_ S2A_TRDM_MinModuleTempDegC_35 : 24|8@1+ (1,0) [0|255] ""  MBMU,PC
 SG_ S2A_TRDM_MinCellVoltMv_35 : 32|16@1+ (1,0) [0|65535] ""  MBMU,PC
 SG_ S2A_TRDM_ThrmlRnwyFltCSC_35 : 48|8@1+ (1,0) [0|255] ""  MBMU,PC

BO_ 2333343588 S2A_SUMDATA13__36: 8 SBMU
 SG_ S2A_TRDM_ThrmlRnwyFltCseMsk_36 : 0|16@1+ (1,0) [0|65535] ""  MBMU,PC
 SG_ S2A_TRDM_MaxModuleTempDegC_36 : 16|8@1+ (1,0) [0|255] ""  MBMU,PC
 SG_ S2A_TRDM_MinModuleTempDegC_36 : 24|8@1+ (1,0) [0|255] ""  MBMU,PC
 SG_ S2A_TRDM_MinCellVoltMv_36 : 32|16@1+ (1,0) [0|65535] ""  MBMU,PC
 SG_ S2A_TRDM_ThrmlRnwyFltCSC_36 : 48|8@1+ (1,0) [0|255] ""  MBMU,PC

CM_ SG_ 2467475281 S2M_IDX_CMD_Type_17 "SBMU发送给MBMU的自动编码命令类型";
CM_ SG_ 2467475281 S2M_IDX_SBMU_Index_17 "SBMU发送给MBMU的SBMU的编码地址";
CM_ SG_ 2467475281 S2M_SBMU_MatchingCode_17 "SBMU发送给MBMU的SBMU的匹配码";
CM_ SG_ 2467475281 S2M_SBMU_Result_17 "SBMU发送给MBMU的编码结果/存储结果 ";
CM_ SG_ 2467475282 S2M_IDX_CMD_Type_18 "SBMU发送给MBMU的自动编码命令类型";
CM_ SG_ 2467475282 S2M_IDX_SBMU_Index_18 "SBMU发送给MBMU的SBMU的编码地址";
CM_ SG_ 2467475282 S2M_SBMU_MatchingCode_18 "SBMU发送给MBMU的SBMU的匹配码";
CM_ SG_ 2467475282 S2M_SBMU_Result_18 "SBMU发送给MBMU的编码结果/存储结果 ";
CM_ SG_ 2467475283 S2M_IDX_CMD_Type_19 "SBMU发送给MBMU的自动编码命令类型";
CM_ SG_ 2467475283 S2M_IDX_SBMU_Index_19 "SBMU发送给MBMU的SBMU的编码地址";
CM_ SG_ 2467475283 S2M_SBMU_MatchingCode_19 "SBMU发送给MBMU的SBMU的匹配码";
CM_ SG_ 2467475283 S2M_SBMU_Result_19 "SBMU发送给MBMU的编码结果/存储结果 ";
CM_ SG_ 2467475284 S2M_IDX_CMD_Type_20 "SBMU发送给MBMU的自动编码命令类型";
CM_ SG_ 2467475284 S2M_IDX_SBMU_Index_20 "SBMU发送给MBMU的SBMU的编码地址";
CM_ SG_ 2467475284 S2M_SBMU_MatchingCode_20 "SBMU发送给MBMU的SBMU的匹配码";
CM_ SG_ 2467475284 S2M_SBMU_Result_20 "SBMU发送给MBMU的编码结果/存储结果 ";
CM_ SG_ 2467475285 S2M_IDX_CMD_Type_21 "SBMU发送给MBMU的自动编码命令类型";
CM_ SG_ 2467475285 S2M_IDX_SBMU_Index_21 "SBMU发送给MBMU的SBMU的编码地址";
CM_ SG_ 2467475285 S2M_SBMU_MatchingCode_21 "SBMU发送给MBMU的SBMU的匹配码";
CM_ SG_ 2467475285 S2M_SBMU_Result_21 "SBMU发送给MBMU的编码结果/存储结果 ";
CM_ SG_ 2467475286 S2M_IDX_CMD_Type_22 "SBMU发送给MBMU的自动编码命令类型";
CM_ SG_ 2467475286 S2M_IDX_SBMU_Index_22 "SBMU发送给MBMU的SBMU的编码地址";
CM_ SG_ 2467475286 S2M_SBMU_MatchingCode_22 "SBMU发送给MBMU的SBMU的匹配码";
CM_ SG_ 2467475286 S2M_SBMU_Result_22 "SBMU发送给MBMU的编码结果/存储结果 ";
CM_ SG_ 2467475287 S2M_IDX_CMD_Type_23 "SBMU发送给MBMU的自动编码命令类型";
CM_ SG_ 2467475287 S2M_IDX_SBMU_Index_23 "SBMU发送给MBMU的SBMU的编码地址";
CM_ SG_ 2467475287 S2M_SBMU_MatchingCode_23 "SBMU发送给MBMU的SBMU的匹配码";
CM_ SG_ 2467475287 S2M_SBMU_Result_23 "SBMU发送给MBMU的编码结果/存储结果 ";
CM_ SG_ 2467475288 S2M_IDX_CMD_Type_24 "SBMU发送给MBMU的自动编码命令类型";
CM_ SG_ 2467475288 S2M_IDX_SBMU_Index_24 "SBMU发送给MBMU的SBMU的编码地址";
CM_ SG_ 2467475288 S2M_SBMU_MatchingCode_24 "SBMU发送给MBMU的SBMU的匹配码";
CM_ SG_ 2467475288 S2M_SBMU_Result_24 "SBMU发送给MBMU的编码结果/存储结果 ";
CM_ SG_ 2467475289 S2M_IDX_CMD_Type_25 "SBMU发送给MBMU的自动编码命令类型";
CM_ SG_ 2467475289 S2M_IDX_SBMU_Index_25 "SBMU发送给MBMU的SBMU的编码地址";
CM_ SG_ 2467475289 S2M_SBMU_MatchingCode_25 "SBMU发送给MBMU的SBMU的匹配码";
CM_ SG_ 2467475289 S2M_SBMU_Result_25 "SBMU发送给MBMU的编码结果/存储结果 ";
CM_ SG_ 2467475290 S2M_IDX_CMD_Type_26 "SBMU发送给MBMU的自动编码命令类型";
CM_ SG_ 2467475290 S2M_IDX_SBMU_Index_26 "SBMU发送给MBMU的SBMU的编码地址";
CM_ SG_ 2467475290 S2M_SBMU_MatchingCode_26 "SBMU发送给MBMU的SBMU的匹配码";
CM_ SG_ 2467475290 S2M_SBMU_Result_26 "SBMU发送给MBMU的编码结果/存储结果 ";
CM_ SG_ 2467475291 S2M_IDX_CMD_Type_27 "SBMU发送给MBMU的自动编码命令类型";
CM_ SG_ 2467475291 S2M_IDX_SBMU_Index_27 "SBMU发送给MBMU的SBMU的编码地址";
CM_ SG_ 2467475291 S2M_SBMU_MatchingCode_27 "SBMU发送给MBMU的SBMU的匹配码";
CM_ SG_ 2467475291 S2M_SBMU_Result_27 "SBMU发送给MBMU的编码结果/存储结果 ";
CM_ SG_ 2467475292 S2M_IDX_CMD_Type_28 "SBMU发送给MBMU的自动编码命令类型";
CM_ SG_ 2467475292 S2M_IDX_SBMU_Index_28 "SBMU发送给MBMU的SBMU的编码地址";
CM_ SG_ 2467475292 S2M_SBMU_MatchingCode_28 "SBMU发送给MBMU的SBMU的匹配码";
CM_ SG_ 2467475292 S2M_SBMU_Result_28 "SBMU发送给MBMU的编码结果/存储结果 ";
CM_ SG_ 2467475293 S2M_IDX_CMD_Type_29 "SBMU发送给MBMU的自动编码命令类型";
CM_ SG_ 2467475293 S2M_IDX_SBMU_Index_29 "SBMU发送给MBMU的SBMU的编码地址";
CM_ SG_ 2467475293 S2M_SBMU_MatchingCode_29 "SBMU发送给MBMU的SBMU的匹配码";
CM_ SG_ 2467475293 S2M_SBMU_Result_29 "SBMU发送给MBMU的编码结果/存储结果 ";
CM_ SG_ 2467475294 S2M_IDX_CMD_Type_30 "SBMU发送给MBMU的自动编码命令类型";
CM_ SG_ 2467475294 S2M_IDX_SBMU_Index_30 "SBMU发送给MBMU的SBMU的编码地址";
CM_ SG_ 2467475294 S2M_SBMU_MatchingCode_30 "SBMU发送给MBMU的SBMU的匹配码";
CM_ SG_ 2467475294 S2M_SBMU_Result_30 "SBMU发送给MBMU的编码结果/存储结果 ";
CM_ SG_ 2467475295 S2M_IDX_CMD_Type_31 "SBMU发送给MBMU的自动编码命令类型";
CM_ SG_ 2467475295 S2M_IDX_SBMU_Index_31 "SBMU发送给MBMU的SBMU的编码地址";
CM_ SG_ 2467475295 S2M_SBMU_MatchingCode_31 "SBMU发送给MBMU的SBMU的匹配码";
CM_ SG_ 2467475295 S2M_SBMU_Result_31 "SBMU发送给MBMU的编码结果/存储结果 ";
CM_ SG_ 2467475296 S2M_IDX_CMD_Type_32 "SBMU发送给MBMU的自动编码命令类型";
CM_ SG_ 2467475296 S2M_IDX_SBMU_Index_32 "SBMU发送给MBMU的SBMU的编码地址";
CM_ SG_ 2467475296 S2M_SBMU_MatchingCode_32 "SBMU发送给MBMU的SBMU的匹配码";
CM_ SG_ 2467475296 S2M_SBMU_Result_32 "SBMU发送给MBMU的编码结果/存储结果 ";
CM_ SG_ 2467475297 S2M_IDX_CMD_Type_33 "SBMU发送给MBMU的自动编码命令类型";
CM_ SG_ 2467475297 S2M_IDX_SBMU_Index_33 "SBMU发送给MBMU的SBMU的编码地址";
CM_ SG_ 2467475297 S2M_SBMU_MatchingCode_33 "SBMU发送给MBMU的SBMU的匹配码";
CM_ SG_ 2467475297 S2M_SBMU_Result_33 "SBMU发送给MBMU的编码结果/存储结果 ";
CM_ SG_ 2467475298 S2M_IDX_CMD_Type_34 "SBMU发送给MBMU的自动编码命令类型";
CM_ SG_ 2467475298 S2M_IDX_SBMU_Index_34 "SBMU发送给MBMU的SBMU的编码地址";
CM_ SG_ 2467475298 S2M_SBMU_MatchingCode_34 "SBMU发送给MBMU的SBMU的匹配码";
CM_ SG_ 2467475298 S2M_SBMU_Result_34 "SBMU发送给MBMU的编码结果/存储结果 ";
CM_ SG_ 2467475299 S2M_IDX_CMD_Type_35 "SBMU发送给MBMU的自动编码命令类型";
CM_ SG_ 2467475299 S2M_IDX_SBMU_Index_35 "SBMU发送给MBMU的SBMU的编码地址";
CM_ SG_ 2467475299 S2M_SBMU_MatchingCode_35 "SBMU发送给MBMU的SBMU的匹配码";
CM_ SG_ 2467475299 S2M_SBMU_Result_35 "SBMU发送给MBMU的编码结果/存储结果 ";
CM_ SG_ 2467475300 S2M_IDX_CMD_Type_36 "SBMU发送给MBMU的自动编码命令类型";
CM_ SG_ 2467475300 S2M_IDX_SBMU_Index_36 "SBMU发送给MBMU的SBMU的编码地址";
CM_ SG_ 2467475300 S2M_SBMU_MatchingCode_36 "SBMU发送给MBMU的SBMU的匹配码";
CM_ SG_ 2467475300 S2M_SBMU_Result_36 "SBMU发送给MBMU的编码结果/存储结果 ";
CM_ SG_ 2467475301 S2M_IDX_CMD_Type_37 "SBMU发送给MBMU的自动编码命令类型";
CM_ SG_ 2467475301 S2M_IDX_SBMU_Index_37 "SBMU发送给MBMU的SBMU的编码地址";
CM_ SG_ 2467475301 S2M_SBMU_MatchingCode_37 "SBMU发送给MBMU的SBMU的匹配码";
CM_ SG_ 2467475301 S2M_SBMU_Result_37 "SBMU发送给MBMU的编码结果/存储结果 ";
CM_ SG_ 2467475302 S2M_IDX_CMD_Type_38 "SBMU发送给MBMU的自动编码命令类型";
CM_ SG_ 2467475302 S2M_IDX_SBMU_Index_38 "SBMU发送给MBMU的SBMU的编码地址";
CM_ SG_ 2467475302 S2M_SBMU_MatchingCode_38 "SBMU发送给MBMU的SBMU的匹配码";
CM_ SG_ 2467475302 S2M_SBMU_Result_38 "SBMU发送给MBMU的编码结果/存储结果 ";
CM_ SG_ 2467475303 S2M_IDX_CMD_Type_39 "SBMU发送给MBMU的自动编码命令类型";
CM_ SG_ 2467475303 S2M_IDX_SBMU_Index_39 "SBMU发送给MBMU的SBMU的编码地址";
CM_ SG_ 2467475303 S2M_SBMU_MatchingCode_39 "SBMU发送给MBMU的SBMU的匹配码";
CM_ SG_ 2467475303 S2M_SBMU_Result_39 "SBMU发送给MBMU的编码结果/存储结果 ";
CM_ SG_ 2467475304 S2M_IDX_CMD_Type_40 "SBMU发送给MBMU的自动编码命令类型";
CM_ SG_ 2467475304 S2M_IDX_SBMU_Index_40 "SBMU发送给MBMU的SBMU的编码地址";
CM_ SG_ 2467475304 S2M_SBMU_MatchingCode_40 "SBMU发送给MBMU的SBMU的匹配码";
CM_ SG_ 2467475304 S2M_SBMU_Result_40 "SBMU发送给MBMU的编码结果/存储结果 ";
CM_ SG_ 2467475305 S2M_IDX_CMD_Type_41 "SBMU发送给MBMU的自动编码命令类型";
CM_ SG_ 2467475305 S2M_IDX_SBMU_Index_41 "SBMU发送给MBMU的SBMU的编码地址";
CM_ SG_ 2467475305 S2M_SBMU_MatchingCode_41 "SBMU发送给MBMU的SBMU的匹配码";
CM_ SG_ 2467475305 S2M_SBMU_Result_41 "SBMU发送给MBMU的编码结果/存储结果 ";
CM_ SG_ 2467475306 S2M_IDX_CMD_Type_42 "SBMU发送给MBMU的自动编码命令类型";
CM_ SG_ 2467475306 S2M_IDX_SBMU_Index_42 "SBMU发送给MBMU的SBMU的编码地址";
CM_ SG_ 2467475306 S2M_SBMU_MatchingCode_42 "SBMU发送给MBMU的SBMU的匹配码";
CM_ SG_ 2467475306 S2M_SBMU_Result_42 "SBMU发送给MBMU的编码结果/存储结果 ";
CM_ SG_ 2467475307 S2M_IDX_CMD_Type_43 "SBMU发送给MBMU的自动编码命令类型";
CM_ SG_ 2467475307 S2M_IDX_SBMU_Index_43 "SBMU发送给MBMU的SBMU的编码地址";
CM_ SG_ 2467475307 S2M_SBMU_MatchingCode_43 "SBMU发送给MBMU的SBMU的匹配码";
CM_ SG_ 2467475307 S2M_SBMU_Result_43 "SBMU发送给MBMU的编码结果/存储结果 ";
CM_ SG_ 2467475308 S2M_IDX_CMD_Type_44 "SBMU发送给MBMU的自动编码命令类型";
CM_ SG_ 2467475308 S2M_IDX_SBMU_Index_44 "SBMU发送给MBMU的SBMU的编码地址";
CM_ SG_ 2467475308 S2M_SBMU_MatchingCode_44 "SBMU发送给MBMU的SBMU的匹配码";
CM_ SG_ 2467475308 S2M_SBMU_Result_44 "SBMU发送给MBMU的编码结果/存储结果 ";
CM_ SG_ 2467475309 S2M_IDX_CMD_Type_45 "SBMU发送给MBMU的自动编码命令类型";
CM_ SG_ 2467475309 S2M_IDX_SBMU_Index_45 "SBMU发送给MBMU的SBMU的编码地址";
CM_ SG_ 2467475309 S2M_SBMU_MatchingCode_45 "SBMU发送给MBMU的SBMU的匹配码";
CM_ SG_ 2467475309 S2M_SBMU_Result_45 "SBMU发送给MBMU的编码结果/存储结果 ";
CM_ SG_ 2467475310 S2M_IDX_CMD_Type_46 "SBMU发送给MBMU的自动编码命令类型";
CM_ SG_ 2467475310 S2M_IDX_SBMU_Index_46 "SBMU发送给MBMU的SBMU的编码地址";
CM_ SG_ 2467475310 S2M_SBMU_MatchingCode_46 "SBMU发送给MBMU的SBMU的匹配码";
CM_ SG_ 2467475310 S2M_SBMU_Result_46 "SBMU发送给MBMU的编码结果/存储结果 ";
CM_ SG_ 2467475311 S2M_IDX_CMD_Type_47 "SBMU发送给MBMU的自动编码命令类型";
CM_ SG_ 2467475311 S2M_IDX_SBMU_Index_47 "SBMU发送给MBMU的SBMU的编码地址";
CM_ SG_ 2467475311 S2M_SBMU_MatchingCode_47 "SBMU发送给MBMU的SBMU的匹配码";
CM_ SG_ 2467475311 S2M_SBMU_Result_47 "SBMU发送给MBMU的编码结果/存储结果 ";
CM_ SG_ 2467475312 S2M_IDX_CMD_Type_48 "SBMU发送给MBMU的自动编码命令类型";
CM_ SG_ 2467475312 S2M_IDX_SBMU_Index_48 "SBMU发送给MBMU的SBMU的编码地址";
CM_ SG_ 2467475312 S2M_SBMU_MatchingCode_48 "SBMU发送给MBMU的SBMU的匹配码";
CM_ SG_ 2467475312 S2M_SBMU_Result_48 "SBMU发送给MBMU的编码结果/存储结果 ";
CM_ SG_ 2467475313 S2M_IDX_CMD_Type_49 "SBMU发送给MBMU的自动编码命令类型";
CM_ SG_ 2467475313 S2M_IDX_SBMU_Index_49 "SBMU发送给MBMU的SBMU的编码地址";
CM_ SG_ 2467475313 S2M_SBMU_MatchingCode_49 "SBMU发送给MBMU的SBMU的匹配码";
CM_ SG_ 2467475313 S2M_SBMU_Result_49 "SBMU发送给MBMU的编码结果/存储结果 ";
CM_ SG_ 2467475314 S2M_IDX_CMD_Type_50 "SBMU发送给MBMU的自动编码命令类型";
CM_ SG_ 2467475314 S2M_IDX_SBMU_Index_50 "SBMU发送给MBMU的SBMU的编码地址";
CM_ SG_ 2467475314 S2M_SBMU_MatchingCode_50 "SBMU发送给MBMU的SBMU的匹配码";
CM_ SG_ 2467475314 S2M_SBMU_Result_50 "SBMU发送给MBMU的编码结果/存储结果 ";
CM_ SG_ 2467475315 S2M_IDX_CMD_Type_51 "SBMU发送给MBMU的自动编码命令类型";
CM_ SG_ 2467475315 S2M_IDX_SBMU_Index_51 "SBMU发送给MBMU的SBMU的编码地址";
CM_ SG_ 2467475315 S2M_SBMU_MatchingCode_51 "SBMU发送给MBMU的SBMU的匹配码";
CM_ SG_ 2467475315 S2M_SBMU_Result_51 "SBMU发送给MBMU的编码结果/存储结果 ";
CM_ SG_ 2467475316 S2M_IDX_CMD_Type_52 "SBMU发送给MBMU的自动编码命令类型";
CM_ SG_ 2467475316 S2M_IDX_SBMU_Index_52 "SBMU发送给MBMU的SBMU的编码地址";
CM_ SG_ 2467475316 S2M_SBMU_MatchingCode_52 "SBMU发送给MBMU的SBMU的匹配码";
CM_ SG_ 2467475316 S2M_SBMU_Result_52 "SBMU发送给MBMU的编码结果/存储结果 ";
CM_ SG_ 2467475317 S2M_IDX_CMD_Type_53 "SBMU发送给MBMU的自动编码命令类型";
CM_ SG_ 2467475317 S2M_IDX_SBMU_Index_53 "SBMU发送给MBMU的SBMU的编码地址";
CM_ SG_ 2467475317 S2M_SBMU_MatchingCode_53 "SBMU发送给MBMU的SBMU的匹配码";
CM_ SG_ 2467475317 S2M_SBMU_Result_53 "SBMU发送给MBMU的编码结果/存储结果 ";
CM_ SG_ 2467475318 S2M_IDX_CMD_Type_54 "SBMU发送给MBMU的自动编码命令类型";
CM_ SG_ 2467475318 S2M_IDX_SBMU_Index_54 "SBMU发送给MBMU的SBMU的编码地址";
CM_ SG_ 2467475318 S2M_SBMU_MatchingCode_54 "SBMU发送给MBMU的SBMU的匹配码";
CM_ SG_ 2467475318 S2M_SBMU_Result_54 "SBMU发送给MBMU的编码结果/存储结果 ";
CM_ SG_ 2467475319 S2M_IDX_CMD_Type_55 "SBMU发送给MBMU的自动编码命令类型";
CM_ SG_ 2467475319 S2M_IDX_SBMU_Index_55 "SBMU发送给MBMU的SBMU的编码地址";
CM_ SG_ 2467475319 S2M_SBMU_MatchingCode_55 "SBMU发送给MBMU的SBMU的匹配码";
CM_ SG_ 2467475319 S2M_SBMU_Result_55 "SBMU发送给MBMU的编码结果/存储结果 ";
CM_ SG_ 2467475320 S2M_IDX_CMD_Type_56 "SBMU发送给MBMU的自动编码命令类型";
CM_ SG_ 2467475320 S2M_IDX_SBMU_Index_56 "SBMU发送给MBMU的SBMU的编码地址";
CM_ SG_ 2467475320 S2M_SBMU_MatchingCode_56 "SBMU发送给MBMU的SBMU的匹配码";
CM_ SG_ 2467475320 S2M_SBMU_Result_56 "SBMU发送给MBMU的编码结果/存储结果 ";
CM_ SG_ 2467475321 S2M_IDX_CMD_Type_57 "SBMU发送给MBMU的自动编码命令类型";
CM_ SG_ 2467475321 S2M_IDX_SBMU_Index_57 "SBMU发送给MBMU的SBMU的编码地址";
CM_ SG_ 2467475321 S2M_SBMU_MatchingCode_57 "SBMU发送给MBMU的SBMU的匹配码";
CM_ SG_ 2467475321 S2M_SBMU_Result_57 "SBMU发送给MBMU的编码结果/存储结果 ";
CM_ SG_ 2467475322 S2M_IDX_CMD_Type_58 "SBMU发送给MBMU的自动编码命令类型";
CM_ SG_ 2467475322 S2M_IDX_SBMU_Index_58 "SBMU发送给MBMU的SBMU的编码地址";
CM_ SG_ 2467475322 S2M_SBMU_MatchingCode_58 "SBMU发送给MBMU的SBMU的匹配码";
CM_ SG_ 2467475322 S2M_SBMU_Result_58 "SBMU发送给MBMU的编码结果/存储结果 ";
CM_ SG_ 2467475323 S2M_IDX_CMD_Type_59 "SBMU发送给MBMU的自动编码命令类型";
CM_ SG_ 2467475323 S2M_IDX_SBMU_Index_59 "SBMU发送给MBMU的SBMU的编码地址";
CM_ SG_ 2467475323 S2M_SBMU_MatchingCode_59 "SBMU发送给MBMU的SBMU的匹配码";
CM_ SG_ 2467475323 S2M_SBMU_Result_59 "SBMU发送给MBMU的编码结果/存储结果 ";
CM_ SG_ 2467475324 S2M_IDX_CMD_Type_60 "SBMU发送给MBMU的自动编码命令类型";
CM_ SG_ 2467475324 S2M_IDX_SBMU_Index_60 "SBMU发送给MBMU的SBMU的编码地址";
CM_ SG_ 2467475324 S2M_SBMU_MatchingCode_60 "SBMU发送给MBMU的SBMU的匹配码";
CM_ SG_ 2467475324 S2M_SBMU_Result_60 "SBMU发送给MBMU的编码结果/存储结果 ";
CM_ SG_ 2467475325 S2M_IDX_CMD_Type_61 "SBMU发送给MBMU的自动编码命令类型";
CM_ SG_ 2467475325 S2M_IDX_SBMU_Index_61 "SBMU发送给MBMU的SBMU的编码地址";
CM_ SG_ 2467475325 S2M_SBMU_MatchingCode_61 "SBMU发送给MBMU的SBMU的匹配码";
CM_ SG_ 2467475325 S2M_SBMU_Result_61 "SBMU发送给MBMU的编码结果/存储结果 ";
CM_ SG_ 2467475326 S2M_IDX_CMD_Type_62 "SBMU发送给MBMU的自动编码命令类型";
CM_ SG_ 2467475326 S2M_IDX_SBMU_Index_62 "SBMU发送给MBMU的SBMU的编码地址";
CM_ SG_ 2467475326 S2M_SBMU_MatchingCode_62 "SBMU发送给MBMU的SBMU的匹配码";
CM_ SG_ 2467475326 S2M_SBMU_Result_62 "SBMU发送给MBMU的编码结果/存储结果 ";
CM_ SG_ 2467475327 S2M_IDX_CMD_Type_63 "SBMU发送给MBMU的自动编码命令类型";
CM_ SG_ 2467475327 S2M_IDX_SBMU_Index_63 "SBMU发送给MBMU的SBMU的编码地址";
CM_ SG_ 2467475327 S2M_SBMU_MatchingCode_63 "SBMU发送给MBMU的SBMU的匹配码";
CM_ SG_ 2467475327 S2M_SBMU_Result_63 "SBMU发送给MBMU的编码结果/存储结果 ";
CM_ SG_ 2467540801 D2M_IDX_CMD_Type_01 "DCDC发送给MBMU的自动编码命令类型";
CM_ SG_ 2467540801 D2M_IDX_DCDC_Index_01 "DCDC发送给MBMU的DCDC的编码地址";
CM_ SG_ 2467540801 D2M_DCDC_MatchingCode_01 "DCDC发送给MBMU的DCDC的匹配码";
CM_ SG_ 2467540801 D2M_DCDC_Result_01 "DCDC发送给MBMU的编码结果";
CM_ SG_ 2467540802 D2M_IDX_CMD_Type_02 "DCDC发送给MBMU的自动编码命令类型";
CM_ SG_ 2467540802 D2M_IDX_DCDC_Index_02 "DCDC发送给MBMU的DCDC的编码地址";
CM_ SG_ 2467540802 D2M_DCDC_MatchingCode_02 "DCDC发送给MBMU的DCDC的匹配码";
CM_ SG_ 2467540802 D2M_DCDC_Result_02 "DCDC发送给MBMU的编码结果";
CM_ SG_ 2467540803 D2M_IDX_CMD_Type_03 "DCDC发送给MBMU的自动编码命令类型";
CM_ SG_ 2467540803 D2M_IDX_DCDC_Index_03 "DCDC发送给MBMU的DCDC的编码地址";
CM_ SG_ 2467540803 D2M_DCDC_MatchingCode_03 "DCDC发送给MBMU的DCDC的匹配码";
CM_ SG_ 2467540803 D2M_DCDC_Result_03 "DCDC发送给MBMU的编码结果";
CM_ SG_ 2467540804 D2M_IDX_CMD_Type_04 "DCDC发送给MBMU的自动编码命令类型";
CM_ SG_ 2467540804 D2M_IDX_DCDC_Index_04 "DCDC发送给MBMU的DCDC的编码地址";
CM_ SG_ 2467540804 D2M_DCDC_MatchingCode_04 "DCDC发送给MBMU的DCDC的匹配码";
CM_ SG_ 2467540804 D2M_DCDC_Result_04 "DCDC发送给MBMU的编码结果";
CM_ SG_ 2467540805 D2M_IDX_CMD_Type_05 "DCDC发送给MBMU的自动编码命令类型";
CM_ SG_ 2467540805 D2M_IDX_DCDC_Index_05 "DCDC发送给MBMU的DCDC的编码地址";
CM_ SG_ 2467540805 D2M_DCDC_MatchingCode_05 "DCDC发送给MBMU的DCDC的匹配码";
CM_ SG_ 2467540805 D2M_DCDC_Result_05 "DCDC发送给MBMU的编码结果";
CM_ SG_ 2467540806 D2M_IDX_CMD_Type_06 "DCDC发送给MBMU的自动编码命令类型";
CM_ SG_ 2467540806 D2M_IDX_DCDC_Index_06 "DCDC发送给MBMU的DCDC的编码地址";
CM_ SG_ 2467540806 D2M_DCDC_MatchingCode_06 "DCDC发送给MBMU的DCDC的匹配码";
CM_ SG_ 2467540806 D2M_DCDC_Result_06 "DCDC发送给MBMU的编码结果";
CM_ SG_ 2467540807 D2M_IDX_CMD_Type_07 "DCDC发送给MBMU的自动编码命令类型";
CM_ SG_ 2467540807 D2M_IDX_DCDC_Index_07 "DCDC发送给MBMU的DCDC的编码地址";
CM_ SG_ 2467540807 D2M_DCDC_MatchingCode_07 "DCDC发送给MBMU的DCDC的匹配码";
CM_ SG_ 2467540807 D2M_DCDC_Result_07 "DCDC发送给MBMU的编码结果";
CM_ SG_ 2467540808 D2M_IDX_CMD_Type_08 "DCDC发送给MBMU的自动编码命令类型";
CM_ SG_ 2467540808 D2M_IDX_DCDC_Index_08 "DCDC发送给MBMU的DCDC的编码地址";
CM_ SG_ 2467540808 D2M_DCDC_MatchingCode_08 "DCDC发送给MBMU的DCDC的匹配码";
CM_ SG_ 2467540808 D2M_DCDC_Result_08 "DCDC发送给MBMU的编码结果";
CM_ SG_ 2467540809 D2M_IDX_CMD_Type_09 "DCDC发送给MBMU的自动编码命令类型";
CM_ SG_ 2467540809 D2M_IDX_DCDC_Index_09 "DCDC发送给MBMU的DCDC的编码地址";
CM_ SG_ 2467540809 D2M_DCDC_MatchingCode_09 "DCDC发送给MBMU的DCDC的匹配码";
CM_ SG_ 2467540809 D2M_DCDC_Result_09 "DCDC发送给MBMU的编码结果";
CM_ SG_ 2467540810 D2M_IDX_CMD_Type_10 "DCDC发送给MBMU的自动编码命令类型";
CM_ SG_ 2467540810 D2M_IDX_DCDC_Index_10 "DCDC发送给MBMU的DCDC的编码地址";
CM_ SG_ 2467540810 D2M_DCDC_MatchingCode_10 "DCDC发送给MBMU的DCDC的匹配码";
CM_ SG_ 2467540810 D2M_DCDC_Result_10 "DCDC发送给MBMU的编码结果";
CM_ SG_ 2467540811 D2M_IDX_CMD_Type_11 "DCDC发送给MBMU的自动编码命令类型";
CM_ SG_ 2467540811 D2M_IDX_DCDC_Index_11 "DCDC发送给MBMU的DCDC的编码地址";
CM_ SG_ 2467540811 D2M_DCDC_MatchingCode_11 "DCDC发送给MBMU的DCDC的匹配码";
CM_ SG_ 2467540811 D2M_DCDC_Result_11 "DCDC发送给MBMU的编码结果";
CM_ SG_ 2467540812 D2M_IDX_CMD_Type_12 "DCDC发送给MBMU的自动编码命令类型";
CM_ SG_ 2467540812 D2M_IDX_DCDC_Index_12 "DCDC发送给MBMU的DCDC的编码地址";
CM_ SG_ 2467540812 D2M_DCDC_MatchingCode_12 "DCDC发送给MBMU的DCDC的匹配码";
CM_ SG_ 2467540812 D2M_DCDC_Result_12 "DCDC发送给MBMU的编码结果";
CM_ SG_ 2467540813 D2M_IDX_CMD_Type_13 "DCDC发送给MBMU的自动编码命令类型";
CM_ SG_ 2467540813 D2M_IDX_DCDC_Index_13 "DCDC发送给MBMU的DCDC的编码地址";
CM_ SG_ 2467540813 D2M_DCDC_MatchingCode_13 "DCDC发送给MBMU的DCDC的匹配码";
CM_ SG_ 2467540813 D2M_DCDC_Result_13 "DCDC发送给MBMU的编码结果";
CM_ SG_ 2467540814 D2M_IDX_CMD_Type_14 "DCDC发送给MBMU的自动编码命令类型";
CM_ SG_ 2467540814 D2M_IDX_DCDC_Index_14 "DCDC发送给MBMU的DCDC的编码地址";
CM_ SG_ 2467540814 D2M_DCDC_MatchingCode_14 "DCDC发送给MBMU的DCDC的匹配码";
CM_ SG_ 2467540814 D2M_DCDC_Result_14 "DCDC发送给MBMU的编码结果";
CM_ SG_ 2467540815 D2M_IDX_CMD_Type_15 "DCDC发送给MBMU的自动编码命令类型";
CM_ SG_ 2467540815 D2M_IDX_DCDC_Index_15 "DCDC发送给MBMU的DCDC的编码地址";
CM_ SG_ 2467540815 D2M_DCDC_MatchingCode_15 "DCDC发送给MBMU的DCDC的匹配码";
CM_ SG_ 2467540815 D2M_DCDC_Result_15 "DCDC发送给MBMU的编码结果";
CM_ SG_ 2467540816 D2M_IDX_CMD_Type_16 "DCDC发送给MBMU的自动编码命令类型";
CM_ SG_ 2467540816 D2M_IDX_DCDC_Index_16 "DCDC发送给MBMU的DCDC的编码地址";
CM_ SG_ 2467540816 D2M_DCDC_MatchingCode_16 "DCDC发送给MBMU的DCDC的匹配码";
CM_ SG_ 2467540816 D2M_DCDC_Result_16 "DCDC发送给MBMU的编码结果";
CM_ SG_ 2467540817 D2M_IDX_CMD_Type_17 "DCDC发送给MBMU的自动编码命令类型";
CM_ SG_ 2467540817 D2M_IDX_DCDC_Index_17 "DCDC发送给MBMU的DCDC的编码地址";
CM_ SG_ 2467540817 D2M_DCDC_MatchingCode_17 "DCDC发送给MBMU的DCDC的匹配码";
CM_ SG_ 2467540817 D2M_DCDC_Result_17 "DCDC发送给MBMU的编码结果";
CM_ SG_ 2467540818 D2M_IDX_CMD_Type_18 "DCDC发送给MBMU的自动编码命令类型";
CM_ SG_ 2467540818 D2M_IDX_DCDC_Index_18 "DCDC发送给MBMU的DCDC的编码地址";
CM_ SG_ 2467540818 D2M_DCDC_MatchingCode_18 "DCDC发送给MBMU的DCDC的匹配码";
CM_ SG_ 2467540818 D2M_DCDC_Result_18 "DCDC发送给MBMU的编码结果";
CM_ SG_ 2467540819 D2M_IDX_CMD_Type_19 "DCDC发送给MBMU的自动编码命令类型";
CM_ SG_ 2467540819 D2M_IDX_DCDC_Index_19 "DCDC发送给MBMU的DCDC的编码地址";
CM_ SG_ 2467540819 D2M_DCDC_MatchingCode_19 "DCDC发送给MBMU的DCDC的匹配码";
CM_ SG_ 2467540819 D2M_DCDC_Result_19 "DCDC发送给MBMU的编码结果";
CM_ SG_ 2467540820 D2M_IDX_CMD_Type_20 "DCDC发送给MBMU的自动编码命令类型";
CM_ SG_ 2467540820 D2M_IDX_DCDC_Index_20 "DCDC发送给MBMU的DCDC的编码地址";
CM_ SG_ 2467540820 D2M_DCDC_MatchingCode_20 "DCDC发送给MBMU的DCDC的匹配码";
CM_ SG_ 2467540820 D2M_DCDC_Result_20 "DCDC发送给MBMU的编码结果";
CM_ SG_ 2467540821 D2M_IDX_CMD_Type_21 "DCDC发送给MBMU的自动编码命令类型";
CM_ SG_ 2467540821 D2M_IDX_DCDC_Index_21 "DCDC发送给MBMU的DCDC的编码地址";
CM_ SG_ 2467540821 D2M_DCDC_MatchingCode_21 "DCDC发送给MBMU的DCDC的匹配码";
CM_ SG_ 2467540821 D2M_DCDC_Result_21 "DCDC发送给MBMU的编码结果";
CM_ SG_ 2467540822 D2M_IDX_CMD_Type_22 "DCDC发送给MBMU的自动编码命令类型";
CM_ SG_ 2467540822 D2M_IDX_DCDC_Index_22 "DCDC发送给MBMU的DCDC的编码地址";
CM_ SG_ 2467540822 D2M_DCDC_MatchingCode_22 "DCDC发送给MBMU的DCDC的匹配码";
CM_ SG_ 2467540822 D2M_DCDC_Result_22 "DCDC发送给MBMU的编码结果";
CM_ SG_ 2467540823 D2M_IDX_CMD_Type_23 "DCDC发送给MBMU的自动编码命令类型";
CM_ SG_ 2467540823 D2M_IDX_DCDC_Index_23 "DCDC发送给MBMU的DCDC的编码地址";
CM_ SG_ 2467540823 D2M_DCDC_MatchingCode_23 "DCDC发送给MBMU的DCDC的匹配码";
CM_ SG_ 2467540823 D2M_DCDC_Result_23 "DCDC发送给MBMU的编码结果";
CM_ SG_ 2467540824 D2M_IDX_CMD_Type_24 "DCDC发送给MBMU的自动编码命令类型";
CM_ SG_ 2467540824 D2M_IDX_DCDC_Index_24 "DCDC发送给MBMU的DCDC的编码地址";
CM_ SG_ 2467540824 D2M_DCDC_MatchingCode_24 "DCDC发送给MBMU的DCDC的匹配码";
CM_ SG_ 2467540824 D2M_DCDC_Result_24 "DCDC发送给MBMU的编码结果";
CM_ SG_ 2467540825 D2M_IDX_CMD_Type_25 "DCDC发送给MBMU的自动编码命令类型";
CM_ SG_ 2467540825 D2M_IDX_DCDC_Index_25 "DCDC发送给MBMU的DCDC的编码地址";
CM_ SG_ 2467540825 D2M_DCDC_MatchingCode_25 "DCDC发送给MBMU的DCDC的匹配码";
CM_ SG_ 2467540825 D2M_DCDC_Result_25 "DCDC发送给MBMU的编码结果";
CM_ SG_ 2467540826 D2M_IDX_CMD_Type_26 "DCDC发送给MBMU的自动编码命令类型";
CM_ SG_ 2467540826 D2M_IDX_DCDC_Index_26 "DCDC发送给MBMU的DCDC的编码地址";
CM_ SG_ 2467540826 D2M_DCDC_MatchingCode_26 "DCDC发送给MBMU的DCDC的匹配码";
CM_ SG_ 2467540826 D2M_DCDC_Result_26 "DCDC发送给MBMU的编码结果";
CM_ SG_ 2467540827 D2M_IDX_CMD_Type_27 "DCDC发送给MBMU的自动编码命令类型";
CM_ SG_ 2467540827 D2M_IDX_DCDC_Index_27 "DCDC发送给MBMU的DCDC的编码地址";
CM_ SG_ 2467540827 D2M_DCDC_MatchingCode_27 "DCDC发送给MBMU的DCDC的匹配码";
CM_ SG_ 2467540827 D2M_DCDC_Result_27 "DCDC发送给MBMU的编码结果";
CM_ SG_ 2467540828 D2M_IDX_CMD_Type_28 "DCDC发送给MBMU的自动编码命令类型";
CM_ SG_ 2467540828 D2M_IDX_DCDC_Index_28 "DCDC发送给MBMU的DCDC的编码地址";
CM_ SG_ 2467540828 D2M_DCDC_MatchingCode_28 "DCDC发送给MBMU的DCDC的匹配码";
CM_ SG_ 2467540828 D2M_DCDC_Result_28 "DCDC发送给MBMU的编码结果";
CM_ SG_ 2467540829 D2M_IDX_CMD_Type_29 "DCDC发送给MBMU的自动编码命令类型";
CM_ SG_ 2467540829 D2M_IDX_DCDC_Index_29 "DCDC发送给MBMU的DCDC的编码地址";
CM_ SG_ 2467540829 D2M_DCDC_MatchingCode_29 "DCDC发送给MBMU的DCDC的匹配码";
CM_ SG_ 2467540829 D2M_DCDC_Result_29 "DCDC发送给MBMU的编码结果";
CM_ SG_ 2467540830 D2M_IDX_CMD_Type_30 "DCDC发送给MBMU的自动编码命令类型";
CM_ SG_ 2467540830 D2M_IDX_DCDC_Index_30 "DCDC发送给MBMU的DCDC的编码地址";
CM_ SG_ 2467540830 D2M_DCDC_MatchingCode_30 "DCDC发送给MBMU的DCDC的匹配码";
CM_ SG_ 2467540830 D2M_DCDC_Result_30 "DCDC发送给MBMU的编码结果";
CM_ SG_ 2467540831 D2M_IDX_CMD_Type_31 "DCDC发送给MBMU的自动编码命令类型";
CM_ SG_ 2467540831 D2M_IDX_DCDC_Index_31 "DCDC发送给MBMU的DCDC的编码地址";
CM_ SG_ 2467540831 D2M_DCDC_MatchingCode_31 "DCDC发送给MBMU的DCDC的匹配码";
CM_ SG_ 2467540831 D2M_DCDC_Result_31 "DCDC发送给MBMU的编码结果";
CM_ SG_ 2467540832 D2M_IDX_CMD_Type_32 "DCDC发送给MBMU的自动编码命令类型";
CM_ SG_ 2467540832 D2M_IDX_DCDC_Index_32 "DCDC发送给MBMU的DCDC的编码地址";
CM_ SG_ 2467540832 D2M_DCDC_MatchingCode_32 "DCDC发送给MBMU的DCDC的匹配码";
CM_ SG_ 2467540832 D2M_DCDC_Result_32 "DCDC发送给MBMU的编码结果";
CM_ SG_ 2467540833 D2M_IDX_CMD_Type_33 "DCDC发送给MBMU的自动编码命令类型";
CM_ SG_ 2467540833 D2M_IDX_DCDC_Index_33 "DCDC发送给MBMU的DCDC的编码地址";
CM_ SG_ 2467540833 D2M_DCDC_MatchingCode_33 "DCDC发送给MBMU的DCDC的匹配码";
CM_ SG_ 2467540833 D2M_DCDC_Result_33 "DCDC发送给MBMU的编码结果";
CM_ SG_ 2467540834 D2M_IDX_CMD_Type_34 "DCDC发送给MBMU的自动编码命令类型";
CM_ SG_ 2467540834 D2M_IDX_DCDC_Index_34 "DCDC发送给MBMU的DCDC的编码地址";
CM_ SG_ 2467540834 D2M_DCDC_MatchingCode_34 "DCDC发送给MBMU的DCDC的匹配码";
CM_ SG_ 2467540834 D2M_DCDC_Result_34 "DCDC发送给MBMU的编码结果";
CM_ SG_ 2467540835 D2M_IDX_CMD_Type_35 "DCDC发送给MBMU的自动编码命令类型";
CM_ SG_ 2467540835 D2M_IDX_DCDC_Index_35 "DCDC发送给MBMU的DCDC的编码地址";
CM_ SG_ 2467540835 D2M_DCDC_MatchingCode_35 "DCDC发送给MBMU的DCDC的匹配码";
CM_ SG_ 2467540835 D2M_DCDC_Result_35 "DCDC发送给MBMU的编码结果";
CM_ SG_ 2467540836 D2M_IDX_CMD_Type_36 "DCDC发送给MBMU的自动编码命令类型";
CM_ SG_ 2467540836 D2M_IDX_DCDC_Index_36 "DCDC发送给MBMU的DCDC的编码地址";
CM_ SG_ 2467540836 D2M_DCDC_MatchingCode_36 "DCDC发送给MBMU的DCDC的匹配码";
CM_ SG_ 2467540836 D2M_DCDC_Result_36 "DCDC发送给MBMU的编码结果";
CM_ SG_ 2467540837 D2M_IDX_CMD_Type_37 "DCDC发送给MBMU的自动编码命令类型";
CM_ SG_ 2467540837 D2M_IDX_DCDC_Index_37 "DCDC发送给MBMU的DCDC的编码地址";
CM_ SG_ 2467540837 D2M_DCDC_MatchingCode_37 "DCDC发送给MBMU的DCDC的匹配码";
CM_ SG_ 2467540837 D2M_DCDC_Result_37 "DCDC发送给MBMU的编码结果";
CM_ SG_ 2467540838 D2M_IDX_CMD_Type_38 "DCDC发送给MBMU的自动编码命令类型";
CM_ SG_ 2467540838 D2M_IDX_DCDC_Index_38 "DCDC发送给MBMU的DCDC的编码地址";
CM_ SG_ 2467540838 D2M_DCDC_MatchingCode_38 "DCDC发送给MBMU的DCDC的匹配码";
CM_ SG_ 2467540838 D2M_DCDC_Result_38 "DCDC发送给MBMU的编码结果";
CM_ SG_ 2467540839 D2M_IDX_CMD_Type_39 "DCDC发送给MBMU的自动编码命令类型";
CM_ SG_ 2467540839 D2M_IDX_DCDC_Index_39 "DCDC发送给MBMU的DCDC的编码地址";
CM_ SG_ 2467540839 D2M_DCDC_MatchingCode_39 "DCDC发送给MBMU的DCDC的匹配码";
CM_ SG_ 2467540839 D2M_DCDC_Result_39 "DCDC发送给MBMU的编码结果";
CM_ SG_ 2467540840 D2M_IDX_CMD_Type_40 "DCDC发送给MBMU的自动编码命令类型";
CM_ SG_ 2467540840 D2M_IDX_DCDC_Index_40 "DCDC发送给MBMU的DCDC的编码地址";
CM_ SG_ 2467540840 D2M_DCDC_MatchingCode_40 "DCDC发送给MBMU的DCDC的匹配码";
CM_ SG_ 2467540840 D2M_DCDC_Result_40 "DCDC发送给MBMU的编码结果";
CM_ SG_ 2467540841 D2M_IDX_CMD_Type_41 "DCDC发送给MBMU的自动编码命令类型";
CM_ SG_ 2467540841 D2M_IDX_DCDC_Index_41 "DCDC发送给MBMU的DCDC的编码地址";
CM_ SG_ 2467540841 D2M_DCDC_MatchingCode_41 "DCDC发送给MBMU的DCDC的匹配码";
CM_ SG_ 2467540841 D2M_DCDC_Result_41 "DCDC发送给MBMU的编码结果";
CM_ SG_ 2467540842 D2M_IDX_CMD_Type_42 "DCDC发送给MBMU的自动编码命令类型";
CM_ SG_ 2467540842 D2M_IDX_DCDC_Index_42 "DCDC发送给MBMU的DCDC的编码地址";
CM_ SG_ 2467540842 D2M_DCDC_MatchingCode_42 "DCDC发送给MBMU的DCDC的匹配码";
CM_ SG_ 2467540842 D2M_DCDC_Result_42 "DCDC发送给MBMU的编码结果";
CM_ SG_ 2467540843 D2M_IDX_CMD_Type_43 "DCDC发送给MBMU的自动编码命令类型";
CM_ SG_ 2467540843 D2M_IDX_DCDC_Index_43 "DCDC发送给MBMU的DCDC的编码地址";
CM_ SG_ 2467540843 D2M_DCDC_MatchingCode_43 "DCDC发送给MBMU的DCDC的匹配码";
CM_ SG_ 2467540843 D2M_DCDC_Result_43 "DCDC发送给MBMU的编码结果";
CM_ SG_ 2467540844 D2M_IDX_CMD_Type_44 "DCDC发送给MBMU的自动编码命令类型";
CM_ SG_ 2467540844 D2M_IDX_DCDC_Index_44 "DCDC发送给MBMU的DCDC的编码地址";
CM_ SG_ 2467540844 D2M_DCDC_MatchingCode_44 "DCDC发送给MBMU的DCDC的匹配码";
CM_ SG_ 2467540844 D2M_DCDC_Result_44 "DCDC发送给MBMU的编码结果";
CM_ SG_ 2467540845 D2M_IDX_CMD_Type_45 "DCDC发送给MBMU的自动编码命令类型";
CM_ SG_ 2467540845 D2M_IDX_DCDC_Index_45 "DCDC发送给MBMU的DCDC的编码地址";
CM_ SG_ 2467540845 D2M_DCDC_MatchingCode_45 "DCDC发送给MBMU的DCDC的匹配码";
CM_ SG_ 2467540845 D2M_DCDC_Result_45 "DCDC发送给MBMU的编码结果";
CM_ SG_ 2467540846 D2M_IDX_CMD_Type_46 "DCDC发送给MBMU的自动编码命令类型";
CM_ SG_ 2467540846 D2M_IDX_DCDC_Index_46 "DCDC发送给MBMU的DCDC的编码地址";
CM_ SG_ 2467540846 D2M_DCDC_MatchingCode_46 "DCDC发送给MBMU的DCDC的匹配码";
CM_ SG_ 2467540846 D2M_DCDC_Result_46 "DCDC发送给MBMU的编码结果";
CM_ SG_ 2467540847 D2M_IDX_CMD_Type_47 "DCDC发送给MBMU的自动编码命令类型";
CM_ SG_ 2467540847 D2M_IDX_DCDC_Index_47 "DCDC发送给MBMU的DCDC的编码地址";
CM_ SG_ 2467540847 D2M_DCDC_MatchingCode_47 "DCDC发送给MBMU的DCDC的匹配码";
CM_ SG_ 2467540847 D2M_DCDC_Result_47 "DCDC发送给MBMU的编码结果";
CM_ SG_ 2467540848 D2M_IDX_CMD_Type_48 "DCDC发送给MBMU的自动编码命令类型";
CM_ SG_ 2467540848 D2M_IDX_DCDC_Index_48 "DCDC发送给MBMU的DCDC的编码地址";
CM_ SG_ 2467540848 D2M_DCDC_MatchingCode_48 "DCDC发送给MBMU的DCDC的匹配码";
CM_ SG_ 2467540848 D2M_DCDC_Result_48 "DCDC发送给MBMU的编码结果";
CM_ SG_ 2467540849 D2M_IDX_CMD_Type_49 "DCDC发送给MBMU的自动编码命令类型";
CM_ SG_ 2467540849 D2M_IDX_DCDC_Index_49 "DCDC发送给MBMU的DCDC的编码地址";
CM_ SG_ 2467540849 D2M_DCDC_MatchingCode_49 "DCDC发送给MBMU的DCDC的匹配码";
CM_ SG_ 2467540849 D2M_DCDC_Result_49 "DCDC发送给MBMU的编码结果";
CM_ SG_ 2467540850 D2M_IDX_CMD_Type_50 "DCDC发送给MBMU的自动编码命令类型";
CM_ SG_ 2467540850 D2M_IDX_DCDC_Index_50 "DCDC发送给MBMU的DCDC的编码地址";
CM_ SG_ 2467540850 D2M_DCDC_MatchingCode_50 "DCDC发送给MBMU的DCDC的匹配码";
CM_ SG_ 2467540850 D2M_DCDC_Result_50 "DCDC发送给MBMU的编码结果";
CM_ SG_ 2467540851 D2M_IDX_CMD_Type_51 "DCDC发送给MBMU的自动编码命令类型";
CM_ SG_ 2467540851 D2M_IDX_DCDC_Index_51 "DCDC发送给MBMU的DCDC的编码地址";
CM_ SG_ 2467540851 D2M_DCDC_MatchingCode_51 "DCDC发送给MBMU的DCDC的匹配码";
CM_ SG_ 2467540851 D2M_DCDC_Result_51 "DCDC发送给MBMU的编码结果";
CM_ SG_ 2467540852 D2M_IDX_CMD_Type_52 "DCDC发送给MBMU的自动编码命令类型";
CM_ SG_ 2467540852 D2M_IDX_DCDC_Index_52 "DCDC发送给MBMU的DCDC的编码地址";
CM_ SG_ 2467540852 D2M_DCDC_MatchingCode_52 "DCDC发送给MBMU的DCDC的匹配码";
CM_ SG_ 2467540852 D2M_DCDC_Result_52 "DCDC发送给MBMU的编码结果";
CM_ SG_ 2467540853 D2M_IDX_CMD_Type_53 "DCDC发送给MBMU的自动编码命令类型";
CM_ SG_ 2467540853 D2M_IDX_DCDC_Index_53 "DCDC发送给MBMU的DCDC的编码地址";
CM_ SG_ 2467540853 D2M_DCDC_MatchingCode_53 "DCDC发送给MBMU的DCDC的匹配码";
CM_ SG_ 2467540853 D2M_DCDC_Result_53 "DCDC发送给MBMU的编码结果";
CM_ SG_ 2467540854 D2M_IDX_CMD_Type_54 "DCDC发送给MBMU的自动编码命令类型";
CM_ SG_ 2467540854 D2M_IDX_DCDC_Index_54 "DCDC发送给MBMU的DCDC的编码地址";
CM_ SG_ 2467540854 D2M_DCDC_MatchingCode_54 "DCDC发送给MBMU的DCDC的匹配码";
CM_ SG_ 2467540854 D2M_DCDC_Result_54 "DCDC发送给MBMU的编码结果";
CM_ SG_ 2467540855 D2M_IDX_CMD_Type_55 "DCDC发送给MBMU的自动编码命令类型";
CM_ SG_ 2467540855 D2M_IDX_DCDC_Index_55 "DCDC发送给MBMU的DCDC的编码地址";
CM_ SG_ 2467540855 D2M_DCDC_MatchingCode_55 "DCDC发送给MBMU的DCDC的匹配码";
CM_ SG_ 2467540855 D2M_DCDC_Result_55 "DCDC发送给MBMU的编码结果";
CM_ SG_ 2467540856 D2M_IDX_CMD_Type_56 "DCDC发送给MBMU的自动编码命令类型";
CM_ SG_ 2467540856 D2M_IDX_DCDC_Index_56 "DCDC发送给MBMU的DCDC的编码地址";
CM_ SG_ 2467540856 D2M_DCDC_MatchingCode_56 "DCDC发送给MBMU的DCDC的匹配码";
CM_ SG_ 2467540856 D2M_DCDC_Result_56 "DCDC发送给MBMU的编码结果";
CM_ SG_ 2467540857 D2M_IDX_CMD_Type_57 "DCDC发送给MBMU的自动编码命令类型";
CM_ SG_ 2467540857 D2M_IDX_DCDC_Index_57 "DCDC发送给MBMU的DCDC的编码地址";
CM_ SG_ 2467540857 D2M_DCDC_MatchingCode_57 "DCDC发送给MBMU的DCDC的匹配码";
CM_ SG_ 2467540857 D2M_DCDC_Result_57 "DCDC发送给MBMU的编码结果";
CM_ SG_ 2467540858 D2M_IDX_CMD_Type_58 "DCDC发送给MBMU的自动编码命令类型";
CM_ SG_ 2467540858 D2M_IDX_DCDC_Index_58 "DCDC发送给MBMU的DCDC的编码地址";
CM_ SG_ 2467540858 D2M_DCDC_MatchingCode_58 "DCDC发送给MBMU的DCDC的匹配码";
CM_ SG_ 2467540858 D2M_DCDC_Result_58 "DCDC发送给MBMU的编码结果";
CM_ SG_ 2467540859 D2M_IDX_CMD_Type_59 "DCDC发送给MBMU的自动编码命令类型";
CM_ SG_ 2467540859 D2M_IDX_DCDC_Index_59 "DCDC发送给MBMU的DCDC的编码地址";
CM_ SG_ 2467540859 D2M_DCDC_MatchingCode_59 "DCDC发送给MBMU的DCDC的匹配码";
CM_ SG_ 2467540859 D2M_DCDC_Result_59 "DCDC发送给MBMU的编码结果";
CM_ SG_ 2467540860 D2M_IDX_CMD_Type_60 "DCDC发送给MBMU的自动编码命令类型";
CM_ SG_ 2467540860 D2M_IDX_DCDC_Index_60 "DCDC发送给MBMU的DCDC的编码地址";
CM_ SG_ 2467540860 D2M_DCDC_MatchingCode_60 "DCDC发送给MBMU的DCDC的匹配码";
CM_ SG_ 2467540860 D2M_DCDC_Result_60 "DCDC发送给MBMU的编码结果";
CM_ SG_ 2467540861 D2M_IDX_CMD_Type_61 "DCDC发送给MBMU的自动编码命令类型";
CM_ SG_ 2467540861 D2M_IDX_DCDC_Index_61 "DCDC发送给MBMU的DCDC的编码地址";
CM_ SG_ 2467540861 D2M_DCDC_MatchingCode_61 "DCDC发送给MBMU的DCDC的匹配码";
CM_ SG_ 2467540861 D2M_DCDC_Result_61 "DCDC发送给MBMU的编码结果";
CM_ SG_ 2467540862 D2M_IDX_CMD_Type_62 "DCDC发送给MBMU的自动编码命令类型";
CM_ SG_ 2467540862 D2M_IDX_DCDC_Index_62 "DCDC发送给MBMU的DCDC的编码地址";
CM_ SG_ 2467540862 D2M_DCDC_MatchingCode_62 "DCDC发送给MBMU的DCDC的匹配码";
CM_ SG_ 2467540862 D2M_DCDC_Result_62 "DCDC发送给MBMU的编码结果";
CM_ SG_ 2467540863 D2M_IDX_CMD_Type_63 "DCDC发送给MBMU的自动编码命令类型";
CM_ SG_ 2467540863 D2M_IDX_DCDC_Index_63 "DCDC发送给MBMU的DCDC的编码地址";
CM_ SG_ 2467540863 D2M_DCDC_MatchingCode_63 "DCDC发送给MBMU的DCDC的匹配码";
CM_ SG_ 2467540863 D2M_DCDC_Result_63 "DCDC发送给MBMU的编码结果";
CM_ SG_ 2333278017 S2A_HIS_ChgCapAh_01 "历史充电容量";
CM_ SG_ 2333278017 S2A_HIS_DisChgCapAh_01 "历史放电容量";
CM_ SG_ 2333278018 S2A_HIS_ChgCapAh_02 "历史充电容量";
CM_ SG_ 2333278018 S2A_HIS_DisChgCapAh_02 "历史放电容量";
CM_ SG_ 2333278019 S2A_HIS_ChgCapAh_03 "历史充电容量";
CM_ SG_ 2333278019 S2A_HIS_DisChgCapAh_03 "历史放电容量";
CM_ SG_ 2333278020 S2A_HIS_ChgCapAh_04 "历史充电容量";
CM_ SG_ 2333278020 S2A_HIS_DisChgCapAh_04 "历史放电容量";
CM_ SG_ 2333278021 S2A_HIS_ChgCapAh_05 "历史充电容量";
CM_ SG_ 2333278021 S2A_HIS_DisChgCapAh_05 "历史放电容量";
CM_ SG_ 2333278022 S2A_HIS_ChgCapAh_06 "历史充电容量";
CM_ SG_ 2333278022 S2A_HIS_DisChgCapAh_06 "历史放电容量";
CM_ SG_ 2333278023 S2A_HIS_ChgCapAh_07 "历史充电容量";
CM_ SG_ 2333278023 S2A_HIS_DisChgCapAh_07 "历史放电容量";
CM_ SG_ 2333278024 S2A_HIS_ChgCapAh_08 "历史充电容量";
CM_ SG_ 2333278024 S2A_HIS_DisChgCapAh_08 "历史放电容量";
CM_ SG_ 2333278025 S2A_HIS_ChgCapAh_09 "历史充电容量";
CM_ SG_ 2333278025 S2A_HIS_DisChgCapAh_09 "历史放电容量";
CM_ SG_ 2333278026 S2A_HIS_ChgCapAh_10 "历史充电容量";
CM_ SG_ 2333278026 S2A_HIS_DisChgCapAh_10 "历史放电容量";
CM_ SG_ 2333278027 S2A_HIS_ChgCapAh_11 "历史充电容量";
CM_ SG_ 2333278027 S2A_HIS_DisChgCapAh_11 "历史放电容量";
CM_ SG_ 2333278028 S2A_HIS_ChgCapAh_12 "历史充电容量";
CM_ SG_ 2333278028 S2A_HIS_DisChgCapAh_12 "历史放电容量";
CM_ SG_ 2333278029 S2A_HIS_ChgCapAh_13 "历史充电容量";
CM_ SG_ 2333278029 S2A_HIS_DisChgCapAh_13 "历史放电容量";
CM_ SG_ 2333278030 S2A_HIS_ChgCapAh_14 "历史充电容量";
CM_ SG_ 2333278030 S2A_HIS_DisChgCapAh_14 "历史放电容量";
CM_ SG_ 2333278031 S2A_HIS_ChgCapAh_15 "历史充电容量";
CM_ SG_ 2333278031 S2A_HIS_DisChgCapAh_15 "历史放电容量";
CM_ SG_ 2333278032 S2A_HIS_ChgCapAh_16 "历史充电容量";
CM_ SG_ 2333278032 S2A_HIS_DisChgCapAh_16 "历史放电容量";
CM_ SG_ 2333278033 S2A_HIS_ChgCapAh_17 "历史充电容量";
CM_ SG_ 2333278033 S2A_HIS_DisChgCapAh_17 "历史放电容量";
CM_ SG_ 2333278034 S2A_HIS_ChgCapAh_18 "历史充电容量";
CM_ SG_ 2333278034 S2A_HIS_DisChgCapAh_18 "历史放电容量";
CM_ SG_ 2333278035 S2A_HIS_ChgCapAh_19 "历史充电容量";
CM_ SG_ 2333278035 S2A_HIS_DisChgCapAh_19 "历史放电容量";
CM_ SG_ 2333278036 S2A_HIS_ChgCapAh_20 "历史充电容量";
CM_ SG_ 2333278036 S2A_HIS_DisChgCapAh_20 "历史放电容量";
CM_ SG_ 2333278037 S2A_HIS_ChgCapAh_21 "历史充电容量";
CM_ SG_ 2333278037 S2A_HIS_DisChgCapAh_21 "历史放电容量";
CM_ SG_ 2333278038 S2A_HIS_ChgCapAh_22 "历史充电容量";
CM_ SG_ 2333278038 S2A_HIS_DisChgCapAh_22 "历史放电容量";
CM_ SG_ 2333278039 S2A_HIS_ChgCapAh_23 "历史充电容量";
CM_ SG_ 2333278039 S2A_HIS_DisChgCapAh_23 "历史放电容量";
CM_ SG_ 2333278040 S2A_HIS_ChgCapAh_24 "历史充电容量";
CM_ SG_ 2333278040 S2A_HIS_DisChgCapAh_24 "历史放电容量";
CM_ SG_ 2333278041 S2A_HIS_ChgCapAh_25 "历史充电容量";
CM_ SG_ 2333278041 S2A_HIS_DisChgCapAh_25 "历史放电容量";
CM_ SG_ 2333278042 S2A_HIS_ChgCapAh_26 "历史充电容量";
CM_ SG_ 2333278042 S2A_HIS_DisChgCapAh_26 "历史放电容量";
CM_ SG_ 2333278043 S2A_HIS_ChgCapAh_27 "历史充电容量";
CM_ SG_ 2333278043 S2A_HIS_DisChgCapAh_27 "历史放电容量";
CM_ SG_ 2333278044 S2A_HIS_ChgCapAh_28 "历史充电容量";
CM_ SG_ 2333278044 S2A_HIS_DisChgCapAh_28 "历史放电容量";
CM_ SG_ 2333278045 S2A_HIS_ChgCapAh_29 "历史充电容量";
CM_ SG_ 2333278045 S2A_HIS_DisChgCapAh_29 "历史放电容量";
CM_ SG_ 2333278046 S2A_HIS_ChgCapAh_30 "历史充电容量";
CM_ SG_ 2333278046 S2A_HIS_DisChgCapAh_30 "历史放电容量";
CM_ SG_ 2333278047 S2A_HIS_ChgCapAh_31 "历史充电容量";
CM_ SG_ 2333278047 S2A_HIS_DisChgCapAh_31 "历史放电容量";
CM_ SG_ 2333278048 S2A_HIS_ChgCapAh_32 "历史充电容量";
CM_ SG_ 2333278048 S2A_HIS_DisChgCapAh_32 "历史放电容量";
CM_ SG_ 2333278049 S2A_HIS_ChgCapAh_33 "历史充电容量";
CM_ SG_ 2333278049 S2A_HIS_DisChgCapAh_33 "历史放电容量";
CM_ SG_ 2333278050 S2A_HIS_ChgCapAh_34 "历史充电容量";
CM_ SG_ 2333278050 S2A_HIS_DisChgCapAh_34 "历史放电容量";
CM_ SG_ 2333278051 S2A_HIS_ChgCapAh_35 "历史充电容量";
CM_ SG_ 2333278051 S2A_HIS_DisChgCapAh_35 "历史放电容量";
CM_ SG_ 2333278052 S2A_HIS_ChgCapAh_36 "历史充电容量";
CM_ SG_ 2333278052 S2A_HIS_DisChgCapAh_36 "历史放电容量";
CM_ SG_ 2333278053 S2A_HIS_ChgCapAh_37 "历史充电容量";
CM_ SG_ 2333278053 S2A_HIS_DisChgCapAh_37 "历史放电容量";
CM_ SG_ 2333278054 S2A_HIS_ChgCapAh_38 "历史充电容量";
CM_ SG_ 2333278054 S2A_HIS_DisChgCapAh_38 "历史放电容量";
CM_ SG_ 2333278055 S2A_HIS_ChgCapAh_39 "历史充电容量";
CM_ SG_ 2333278055 S2A_HIS_DisChgCapAh_39 "历史放电容量";
CM_ SG_ 2333278056 S2A_HIS_ChgCapAh_40 "历史充电容量";
CM_ SG_ 2333278056 S2A_HIS_DisChgCapAh_40 "历史放电容量";
CM_ SG_ 2333278057 S2A_HIS_ChgCapAh_41 "历史充电容量";
CM_ SG_ 2333278057 S2A_HIS_DisChgCapAh_41 "历史放电容量";
CM_ SG_ 2333278058 S2A_HIS_ChgCapAh_42 "历史充电容量";
CM_ SG_ 2333278058 S2A_HIS_DisChgCapAh_42 "历史放电容量";
CM_ SG_ 2333278059 S2A_HIS_ChgCapAh_43 "历史充电容量";
CM_ SG_ 2333278059 S2A_HIS_DisChgCapAh_43 "历史放电容量";
CM_ SG_ 2333278060 S2A_HIS_ChgCapAh_44 "历史充电容量";
CM_ SG_ 2333278060 S2A_HIS_DisChgCapAh_44 "历史放电容量";
CM_ SG_ 2333278061 S2A_HIS_ChgCapAh_45 "历史充电容量";
CM_ SG_ 2333278061 S2A_HIS_DisChgCapAh_45 "历史放电容量";
CM_ SG_ 2333278062 S2A_HIS_ChgCapAh_46 "历史充电容量";
CM_ SG_ 2333278062 S2A_HIS_DisChgCapAh_46 "历史放电容量";
CM_ SG_ 2333278063 S2A_HIS_ChgCapAh_47 "历史充电容量";
CM_ SG_ 2333278063 S2A_HIS_DisChgCapAh_47 "历史放电容量";
CM_ SG_ 2333278064 S2A_HIS_ChgCapAh_48 "历史充电容量";
CM_ SG_ 2333278064 S2A_HIS_DisChgCapAh_48 "历史放电容量";
CM_ SG_ 2333278065 S2A_HIS_ChgCapAh_49 "历史充电容量";
CM_ SG_ 2333278065 S2A_HIS_DisChgCapAh_49 "历史放电容量";
CM_ SG_ 2333278066 S2A_HIS_ChgCapAh_50 "历史充电容量";
CM_ SG_ 2333278066 S2A_HIS_DisChgCapAh_50 "历史放电容量";
CM_ SG_ 2333278067 S2A_HIS_ChgCapAh_51 "历史充电容量";
CM_ SG_ 2333278067 S2A_HIS_DisChgCapAh_51 "历史放电容量";
CM_ SG_ 2333278068 S2A_HIS_ChgCapAh_52 "历史充电容量";
CM_ SG_ 2333278068 S2A_HIS_DisChgCapAh_52 "历史放电容量";
CM_ SG_ 2333278069 S2A_HIS_ChgCapAh_53 "历史充电容量";
CM_ SG_ 2333278069 S2A_HIS_DisChgCapAh_53 "历史放电容量";
CM_ SG_ 2333278070 S2A_HIS_ChgCapAh_54 "历史充电容量";
CM_ SG_ 2333278070 S2A_HIS_DisChgCapAh_54 "历史放电容量";
CM_ SG_ 2333278071 S2A_HIS_ChgCapAh_55 "历史充电容量";
CM_ SG_ 2333278071 S2A_HIS_DisChgCapAh_55 "历史放电容量";
CM_ SG_ 2333278072 S2A_HIS_ChgCapAh_56 "历史充电容量";
CM_ SG_ 2333278072 S2A_HIS_DisChgCapAh_56 "历史放电容量";
CM_ SG_ 2333278073 S2A_HIS_ChgCapAh_57 "历史充电容量";
CM_ SG_ 2333278073 S2A_HIS_DisChgCapAh_57 "历史放电容量";
CM_ SG_ 2333278074 S2A_HIS_ChgCapAh_58 "历史充电容量";
CM_ SG_ 2333278074 S2A_HIS_DisChgCapAh_58 "历史放电容量";
CM_ SG_ 2333278075 S2A_HIS_ChgCapAh_59 "历史充电容量";
CM_ SG_ 2333278075 S2A_HIS_DisChgCapAh_59 "历史放电容量";
CM_ SG_ 2333278076 S2A_HIS_ChgCapAh_60 "历史充电容量";
CM_ SG_ 2333278076 S2A_HIS_DisChgCapAh_60 "历史放电容量";
CM_ SG_ 2333278077 S2A_HIS_ChgCapAh_61 "历史充电容量";
CM_ SG_ 2333278077 S2A_HIS_DisChgCapAh_61 "历史放电容量";
CM_ SG_ 2333278078 S2A_HIS_ChgCapAh_62 "历史充电容量";
CM_ SG_ 2333278078 S2A_HIS_DisChgCapAh_62 "历史放电容量";
CM_ SG_ 2333278079 S2A_HIS_ChgCapAh_63 "历史充电容量";
CM_ SG_ 2333278079 S2A_HIS_DisChgCapAh_63 "历史放电容量";
CM_ SG_ 2333343553 S2A_TRDM_ThrmlRnwyFltCseMsk_01 "热失控原因（每一位代表一种原因）";
CM_ SG_ 2333343553 S2A_TRDM_MaxModuleTempDegC_01 "热失控发生时的最大温度";
CM_ SG_ 2333343553 S2A_TRDM_MinModuleTempDegC_01 "热失控发生时的最小温度";
CM_ SG_ 2333343553 S2A_TRDM_MinCellVoltMv_01 "热失控发生时的最小电芯电压";
CM_ SG_ 2333343553 S2A_TRDM_ThrmlRnwyFltCSC_01 "发生热失控的CSC编号";
CM_ SG_ 2333343554 S2A_TRDM_ThrmlRnwyFltCseMsk_02 "热失控原因（每一位代表一种原因）";
CM_ SG_ 2333343554 S2A_TRDM_MaxModuleTempDegC_02 "热失控发生时的最大温度";
CM_ SG_ 2333343554 S2A_TRDM_MinModuleTempDegC_02 "热失控发生时的最小温度";
CM_ SG_ 2333343554 S2A_TRDM_MinCellVoltMv_02 "热失控发生时的最小电芯电压";
CM_ SG_ 2333343554 S2A_TRDM_ThrmlRnwyFltCSC_02 "发生热失控的CSC编号";
CM_ SG_ 2333343555 S2A_TRDM_ThrmlRnwyFltCseMsk_03 "热失控原因（每一位代表一种原因）";
CM_ SG_ 2333343555 S2A_TRDM_MaxModuleTempDegC_03 "热失控发生时的最大温度";
CM_ SG_ 2333343555 S2A_TRDM_MinModuleTempDegC_03 "热失控发生时的最小温度";
CM_ SG_ 2333343555 S2A_TRDM_MinCellVoltMv_03 "热失控发生时的最小电芯电压";
CM_ SG_ 2333343555 S2A_TRDM_ThrmlRnwyFltCSC_03 "发生热失控的CSC编号";
CM_ SG_ 2333343556 S2A_TRDM_ThrmlRnwyFltCseMsk_04 "热失控原因（每一位代表一种原因）";
CM_ SG_ 2333343556 S2A_TRDM_MaxModuleTempDegC_04 "热失控发生时的最大温度";
CM_ SG_ 2333343556 S2A_TRDM_MinModuleTempDegC_04 "热失控发生时的最小温度";
CM_ SG_ 2333343556 S2A_TRDM_MinCellVoltMv_04 "热失控发生时的最小电芯电压";
CM_ SG_ 2333343556 S2A_TRDM_ThrmlRnwyFltCSC_04 "发生热失控的CSC编号";
CM_ SG_ 2333343557 S2A_TRDM_ThrmlRnwyFltCseMsk_05 "热失控原因（每一位代表一种原因）";
CM_ SG_ 2333343557 S2A_TRDM_MaxModuleTempDegC_05 "热失控发生时的最大温度";
CM_ SG_ 2333343557 S2A_TRDM_MinModuleTempDegC_05 "热失控发生时的最小温度";
CM_ SG_ 2333343557 S2A_TRDM_MinCellVoltMv_05 "热失控发生时的最小电芯电压";
CM_ SG_ 2333343557 S2A_TRDM_ThrmlRnwyFltCSC_05 "发生热失控的CSC编号";
CM_ SG_ 2333343558 S2A_TRDM_ThrmlRnwyFltCseMsk_06 "热失控原因（每一位代表一种原因）";
CM_ SG_ 2333343558 S2A_TRDM_MaxModuleTempDegC_06 "热失控发生时的最大温度";
CM_ SG_ 2333343558 S2A_TRDM_MinModuleTempDegC_06 "热失控发生时的最小温度";
CM_ SG_ 2333343558 S2A_TRDM_MinCellVoltMv_06 "热失控发生时的最小电芯电压";
CM_ SG_ 2333343558 S2A_TRDM_ThrmlRnwyFltCSC_06 "发生热失控的CSC编号";
CM_ SG_ 2333343559 S2A_TRDM_ThrmlRnwyFltCseMsk_07 "热失控原因（每一位代表一种原因）";
CM_ SG_ 2333343559 S2A_TRDM_MaxModuleTempDegC_07 "热失控发生时的最大温度";
CM_ SG_ 2333343559 S2A_TRDM_MinModuleTempDegC_07 "热失控发生时的最小温度";
CM_ SG_ 2333343559 S2A_TRDM_MinCellVoltMv_07 "热失控发生时的最小电芯电压";
CM_ SG_ 2333343559 S2A_TRDM_ThrmlRnwyFltCSC_07 "发生热失控的CSC编号";
CM_ SG_ 2333343560 S2A_TRDM_ThrmlRnwyFltCseMsk_08 "热失控原因（每一位代表一种原因）";
CM_ SG_ 2333343560 S2A_TRDM_MaxModuleTempDegC_08 "热失控发生时的最大温度";
CM_ SG_ 2333343560 S2A_TRDM_MinModuleTempDegC_08 "热失控发生时的最小温度";
CM_ SG_ 2333343560 S2A_TRDM_MinCellVoltMv_08 "热失控发生时的最小电芯电压";
CM_ SG_ 2333343560 S2A_TRDM_ThrmlRnwyFltCSC_08 "发生热失控的CSC编号";
CM_ SG_ 2333343561 S2A_TRDM_ThrmlRnwyFltCseMsk_09 "热失控原因（每一位代表一种原因）";
CM_ SG_ 2333343561 S2A_TRDM_MaxModuleTempDegC_09 "热失控发生时的最大温度";
CM_ SG_ 2333343561 S2A_TRDM_MinModuleTempDegC_09 "热失控发生时的最小温度";
CM_ SG_ 2333343561 S2A_TRDM_MinCellVoltMv_09 "热失控发生时的最小电芯电压";
CM_ SG_ 2333343561 S2A_TRDM_ThrmlRnwyFltCSC_09 "发生热失控的CSC编号";
CM_ SG_ 2333343562 S2A_TRDM_ThrmlRnwyFltCseMsk_10 "热失控原因（每一位代表一种原因）";
CM_ SG_ 2333343562 S2A_TRDM_MaxModuleTempDegC_10 "热失控发生时的最大温度";
CM_ SG_ 2333343562 S2A_TRDM_MinModuleTempDegC_10 "热失控发生时的最小温度";
CM_ SG_ 2333343562 S2A_TRDM_MinCellVoltMv_10 "热失控发生时的最小电芯电压";
CM_ SG_ 2333343562 S2A_TRDM_ThrmlRnwyFltCSC_10 "发生热失控的CSC编号";
CM_ SG_ 2333343563 S2A_TRDM_ThrmlRnwyFltCseMsk_11 "热失控原因（每一位代表一种原因）";
CM_ SG_ 2333343563 S2A_TRDM_MaxModuleTempDegC_11 "热失控发生时的最大温度";
CM_ SG_ 2333343563 S2A_TRDM_MinModuleTempDegC_11 "热失控发生时的最小温度";
CM_ SG_ 2333343563 S2A_TRDM_MinCellVoltMv_11 "热失控发生时的最小电芯电压";
CM_ SG_ 2333343563 S2A_TRDM_ThrmlRnwyFltCSC_11 "发生热失控的CSC编号";
CM_ SG_ 2333343564 S2A_TRDM_ThrmlRnwyFltCseMsk_12 "热失控原因（每一位代表一种原因）";
CM_ SG_ 2333343564 S2A_TRDM_MaxModuleTempDegC_12 "热失控发生时的最大温度";
CM_ SG_ 2333343564 S2A_TRDM_MinModuleTempDegC_12 "热失控发生时的最小温度";
CM_ SG_ 2333343564 S2A_TRDM_MinCellVoltMv_12 "热失控发生时的最小电芯电压";
CM_ SG_ 2333343564 S2A_TRDM_ThrmlRnwyFltCSC_12 "发生热失控的CSC编号";
CM_ SG_ 2333343565 S2A_TRDM_ThrmlRnwyFltCseMsk_13 "热失控原因（每一位代表一种原因）";
CM_ SG_ 2333343565 S2A_TRDM_MaxModuleTempDegC_13 "热失控发生时的最大温度";
CM_ SG_ 2333343565 S2A_TRDM_MinModuleTempDegC_13 "热失控发生时的最小温度";
CM_ SG_ 2333343565 S2A_TRDM_MinCellVoltMv_13 "热失控发生时的最小电芯电压";
CM_ SG_ 2333343565 S2A_TRDM_ThrmlRnwyFltCSC_13 "发生热失控的CSC编号";
CM_ SG_ 2333343566 S2A_TRDM_ThrmlRnwyFltCseMsk_14 "热失控原因（每一位代表一种原因）";
CM_ SG_ 2333343566 S2A_TRDM_MaxModuleTempDegC_14 "热失控发生时的最大温度";
CM_ SG_ 2333343566 S2A_TRDM_MinModuleTempDegC_14 "热失控发生时的最小温度";
CM_ SG_ 2333343566 S2A_TRDM_MinCellVoltMv_14 "热失控发生时的最小电芯电压";
CM_ SG_ 2333343566 S2A_TRDM_ThrmlRnwyFltCSC_14 "发生热失控的CSC编号";
CM_ SG_ 2333343567 S2A_TRDM_ThrmlRnwyFltCseMsk_15 "热失控原因（每一位代表一种原因）";
CM_ SG_ 2333343567 S2A_TRDM_MaxModuleTempDegC_15 "热失控发生时的最大温度";
CM_ SG_ 2333343567 S2A_TRDM_MinModuleTempDegC_15 "热失控发生时的最小温度";
CM_ SG_ 2333343567 S2A_TRDM_MinCellVoltMv_15 "热失控发生时的最小电芯电压";
CM_ SG_ 2333343567 S2A_TRDM_ThrmlRnwyFltCSC_15 "发生热失控的CSC编号";
CM_ SG_ 2333343568 S2A_TRDM_ThrmlRnwyFltCseMsk_16 "热失控原因（每一位代表一种原因）";
CM_ SG_ 2333343568 S2A_TRDM_MaxModuleTempDegC_16 "热失控发生时的最大温度";
CM_ SG_ 2333343568 S2A_TRDM_MinModuleTempDegC_16 "热失控发生时的最小温度";
CM_ SG_ 2333343568 S2A_TRDM_MinCellVoltMv_16 "热失控发生时的最小电芯电压";
CM_ SG_ 2333343568 S2A_TRDM_ThrmlRnwyFltCSC_16 "发生热失控的CSC编号";
CM_ SG_ 2333343569 S2A_TRDM_ThrmlRnwyFltCseMsk_17 "热失控原因（每一位代表一种原因）";
CM_ SG_ 2333343569 S2A_TRDM_MaxModuleTempDegC_17 "热失控发生时的最大温度";
CM_ SG_ 2333343569 S2A_TRDM_MinModuleTempDegC_17 "热失控发生时的最小温度";
CM_ SG_ 2333343569 S2A_TRDM_MinCellVoltMv_17 "热失控发生时的最小电芯电压";
CM_ SG_ 2333343569 S2A_TRDM_ThrmlRnwyFltCSC_17 "发生热失控的CSC编号";
CM_ SG_ 2333343570 S2A_TRDM_ThrmlRnwyFltCseMsk_18 "热失控原因（每一位代表一种原因）";
CM_ SG_ 2333343570 S2A_TRDM_MaxModuleTempDegC_18 "热失控发生时的最大温度";
CM_ SG_ 2333343570 S2A_TRDM_MinModuleTempDegC_18 "热失控发生时的最小温度";
CM_ SG_ 2333343570 S2A_TRDM_MinCellVoltMv_18 "热失控发生时的最小电芯电压";
CM_ SG_ 2333343570 S2A_TRDM_ThrmlRnwyFltCSC_18 "发生热失控的CSC编号";
CM_ SG_ 2333343571 S2A_TRDM_ThrmlRnwyFltCseMsk_19 "热失控原因（每一位代表一种原因）";
CM_ SG_ 2333343571 S2A_TRDM_MaxModuleTempDegC_19 "热失控发生时的最大温度";
CM_ SG_ 2333343571 S2A_TRDM_MinModuleTempDegC_19 "热失控发生时的最小温度";
CM_ SG_ 2333343571 S2A_TRDM_MinCellVoltMv_19 "热失控发生时的最小电芯电压";
CM_ SG_ 2333343571 S2A_TRDM_ThrmlRnwyFltCSC_19 "发生热失控的CSC编号";
CM_ SG_ 2333343572 S2A_TRDM_ThrmlRnwyFltCseMsk_20 "热失控原因（每一位代表一种原因）";
CM_ SG_ 2333343572 S2A_TRDM_MaxModuleTempDegC_20 "热失控发生时的最大温度";
CM_ SG_ 2333343572 S2A_TRDM_MinModuleTempDegC_20 "热失控发生时的最小温度";
CM_ SG_ 2333343572 S2A_TRDM_MinCellVoltMv_20 "热失控发生时的最小电芯电压";
CM_ SG_ 2333343572 S2A_TRDM_ThrmlRnwyFltCSC_20 "发生热失控的CSC编号";
CM_ SG_ 2333343573 S2A_TRDM_ThrmlRnwyFltCseMsk_21 "热失控原因（每一位代表一种原因）";
CM_ SG_ 2333343573 S2A_TRDM_MaxModuleTempDegC_21 "热失控发生时的最大温度";
CM_ SG_ 2333343573 S2A_TRDM_MinModuleTempDegC_21 "热失控发生时的最小温度";
CM_ SG_ 2333343573 S2A_TRDM_MinCellVoltMv_21 "热失控发生时的最小电芯电压";
CM_ SG_ 2333343573 S2A_TRDM_ThrmlRnwyFltCSC_21 "发生热失控的CSC编号";
CM_ SG_ 2333343574 S2A_TRDM_ThrmlRnwyFltCseMsk_22 "热失控原因（每一位代表一种原因）";
CM_ SG_ 2333343574 S2A_TRDM_MaxModuleTempDegC_22 "热失控发生时的最大温度";
CM_ SG_ 2333343574 S2A_TRDM_MinModuleTempDegC_22 "热失控发生时的最小温度";
CM_ SG_ 2333343574 S2A_TRDM_MinCellVoltMv_22 "热失控发生时的最小电芯电压";
CM_ SG_ 2333343574 S2A_TRDM_ThrmlRnwyFltCSC_22 "发生热失控的CSC编号";
CM_ SG_ 2333343575 S2A_TRDM_ThrmlRnwyFltCseMsk_23 "热失控原因（每一位代表一种原因）";
CM_ SG_ 2333343575 S2A_TRDM_MaxModuleTempDegC_23 "热失控发生时的最大温度";
CM_ SG_ 2333343575 S2A_TRDM_MinModuleTempDegC_23 "热失控发生时的最小温度";
CM_ SG_ 2333343575 S2A_TRDM_MinCellVoltMv_23 "热失控发生时的最小电芯电压";
CM_ SG_ 2333343575 S2A_TRDM_ThrmlRnwyFltCSC_23 "发生热失控的CSC编号";
CM_ SG_ 2333343576 S2A_TRDM_ThrmlRnwyFltCseMsk_24 "热失控原因（每一位代表一种原因）";
CM_ SG_ 2333343576 S2A_TRDM_MaxModuleTempDegC_24 "热失控发生时的最大温度";
CM_ SG_ 2333343576 S2A_TRDM_MinModuleTempDegC_24 "热失控发生时的最小温度";
CM_ SG_ 2333343576 S2A_TRDM_MinCellVoltMv_24 "热失控发生时的最小电芯电压";
CM_ SG_ 2333343576 S2A_TRDM_ThrmlRnwyFltCSC_24 "发生热失控的CSC编号";
CM_ SG_ 2333343577 S2A_TRDM_ThrmlRnwyFltCseMsk_25 "热失控原因（每一位代表一种原因）";
CM_ SG_ 2333343577 S2A_TRDM_MaxModuleTempDegC_25 "热失控发生时的最大温度";
CM_ SG_ 2333343577 S2A_TRDM_MinModuleTempDegC_25 "热失控发生时的最小温度";
CM_ SG_ 2333343577 S2A_TRDM_MinCellVoltMv_25 "热失控发生时的最小电芯电压";
CM_ SG_ 2333343577 S2A_TRDM_ThrmlRnwyFltCSC_25 "发生热失控的CSC编号";
CM_ SG_ 2333343578 S2A_TRDM_ThrmlRnwyFltCseMsk_26 "热失控原因（每一位代表一种原因）";
CM_ SG_ 2333343578 S2A_TRDM_MaxModuleTempDegC_26 "热失控发生时的最大温度";
CM_ SG_ 2333343578 S2A_TRDM_MinModuleTempDegC_26 "热失控发生时的最小温度";
CM_ SG_ 2333343578 S2A_TRDM_MinCellVoltMv_26 "热失控发生时的最小电芯电压";
CM_ SG_ 2333343578 S2A_TRDM_ThrmlRnwyFltCSC_26 "发生热失控的CSC编号";
CM_ SG_ 2333343579 S2A_TRDM_ThrmlRnwyFltCseMsk_27 "热失控原因（每一位代表一种原因）";
CM_ SG_ 2333343579 S2A_TRDM_MaxModuleTempDegC_27 "热失控发生时的最大温度";
CM_ SG_ 2333343579 S2A_TRDM_MinModuleTempDegC_27 "热失控发生时的最小温度";
CM_ SG_ 2333343579 S2A_TRDM_MinCellVoltMv_27 "热失控发生时的最小电芯电压";
CM_ SG_ 2333343579 S2A_TRDM_ThrmlRnwyFltCSC_27 "发生热失控的CSC编号";
CM_ SG_ 2333343580 S2A_TRDM_ThrmlRnwyFltCseMsk_28 "热失控原因（每一位代表一种原因）";
CM_ SG_ 2333343580 S2A_TRDM_MaxModuleTempDegC_28 "热失控发生时的最大温度";
CM_ SG_ 2333343580 S2A_TRDM_MinModuleTempDegC_28 "热失控发生时的最小温度";
CM_ SG_ 2333343580 S2A_TRDM_MinCellVoltMv_28 "热失控发生时的最小电芯电压";
CM_ SG_ 2333343580 S2A_TRDM_ThrmlRnwyFltCSC_28 "发生热失控的CSC编号";
CM_ SG_ 2333343581 S2A_TRDM_ThrmlRnwyFltCseMsk_29 "热失控原因（每一位代表一种原因）";
CM_ SG_ 2333343581 S2A_TRDM_MaxModuleTempDegC_29 "热失控发生时的最大温度";
CM_ SG_ 2333343581 S2A_TRDM_MinModuleTempDegC_29 "热失控发生时的最小温度";
CM_ SG_ 2333343581 S2A_TRDM_MinCellVoltMv_29 "热失控发生时的最小电芯电压";
CM_ SG_ 2333343581 S2A_TRDM_ThrmlRnwyFltCSC_29 "发生热失控的CSC编号";
CM_ SG_ 2333343582 S2A_TRDM_ThrmlRnwyFltCseMsk_30 "热失控原因（每一位代表一种原因）";
CM_ SG_ 2333343582 S2A_TRDM_MaxModuleTempDegC_30 "热失控发生时的最大温度";
CM_ SG_ 2333343582 S2A_TRDM_MinModuleTempDegC_30 "热失控发生时的最小温度";
CM_ SG_ 2333343582 S2A_TRDM_MinCellVoltMv_30 "热失控发生时的最小电芯电压";
CM_ SG_ 2333343582 S2A_TRDM_ThrmlRnwyFltCSC_30 "发生热失控的CSC编号";
CM_ SG_ 2333343583 S2A_TRDM_ThrmlRnwyFltCseMsk_31 "热失控原因（每一位代表一种原因）";
CM_ SG_ 2333343583 S2A_TRDM_MaxModuleTempDegC_31 "热失控发生时的最大温度";
CM_ SG_ 2333343583 S2A_TRDM_MinModuleTempDegC_31 "热失控发生时的最小温度";
CM_ SG_ 2333343583 S2A_TRDM_MinCellVoltMv_31 "热失控发生时的最小电芯电压";
CM_ SG_ 2333343583 S2A_TRDM_ThrmlRnwyFltCSC_31 "发生热失控的CSC编号";
CM_ SG_ 2333343584 S2A_TRDM_ThrmlRnwyFltCseMsk_32 "热失控原因（每一位代表一种原因）";
CM_ SG_ 2333343584 S2A_TRDM_MaxModuleTempDegC_32 "热失控发生时的最大温度";
CM_ SG_ 2333343584 S2A_TRDM_MinModuleTempDegC_32 "热失控发生时的最小温度";
CM_ SG_ 2333343584 S2A_TRDM_MinCellVoltMv_32 "热失控发生时的最小电芯电压";
CM_ SG_ 2333343584 S2A_TRDM_ThrmlRnwyFltCSC_32 "发生热失控的CSC编号";
CM_ SG_ 2333343585 S2A_TRDM_ThrmlRnwyFltCseMsk_33 "热失控原因（每一位代表一种原因）";
CM_ SG_ 2333343585 S2A_TRDM_MaxModuleTempDegC_33 "热失控发生时的最大温度";
CM_ SG_ 2333343585 S2A_TRDM_MinModuleTempDegC_33 "热失控发生时的最小温度";
CM_ SG_ 2333343585 S2A_TRDM_MinCellVoltMv_33 "热失控发生时的最小电芯电压";
CM_ SG_ 2333343585 S2A_TRDM_ThrmlRnwyFltCSC_33 "发生热失控的CSC编号";
CM_ SG_ 2333343586 S2A_TRDM_ThrmlRnwyFltCseMsk_34 "热失控原因（每一位代表一种原因）";
CM_ SG_ 2333343586 S2A_TRDM_MaxModuleTempDegC_34 "热失控发生时的最大温度";
CM_ SG_ 2333343586 S2A_TRDM_MinModuleTempDegC_34 "热失控发生时的最小温度";
CM_ SG_ 2333343586 S2A_TRDM_MinCellVoltMv_34 "热失控发生时的最小电芯电压";
CM_ SG_ 2333343586 S2A_TRDM_ThrmlRnwyFltCSC_34 "发生热失控的CSC编号";
CM_ SG_ 2333343587 S2A_TRDM_ThrmlRnwyFltCseMsk_35 "热失控原因（每一位代表一种原因）";
CM_ SG_ 2333343587 S2A_TRDM_MaxModuleTempDegC_35 "热失控发生时的最大温度";
CM_ SG_ 2333343587 S2A_TRDM_MinModuleTempDegC_35 "热失控发生时的最小温度";
CM_ SG_ 2333343587 S2A_TRDM_MinCellVoltMv_35 "热失控发生时的最小电芯电压";
CM_ SG_ 2333343587 S2A_TRDM_ThrmlRnwyFltCSC_35 "发生热失控的CSC编号";
CM_ SG_ 2333343588 S2A_TRDM_ThrmlRnwyFltCseMsk_36 "热失控原因（每一位代表一种原因）";
CM_ SG_ 2333343588 S2A_TRDM_MaxModuleTempDegC_36 "热失控发生时的最大温度";
CM_ SG_ 2333343588 S2A_TRDM_MinModuleTempDegC_36 "热失控发生时的最小温度";
CM_ SG_ 2333343588 S2A_TRDM_MinCellVoltMv_36 "热失控发生时的最小电芯电压";
CM_ SG_ 2333343588 S2A_TRDM_ThrmlRnwyFltCSC_36 "发生热失控的CSC编号";
VAL_ 2467475281 S2M_IDX_CMD_Type_17 0 "Invalid" 1 "Request address confirmation" 2 "Reserve" 3 "Sucess" ;
VAL_ 2467475281 S2M_IDX_SBMU_Index_17 0 "Initial Index" 1 "Index 1" 2 "Index 2" 3 "Index 3" 4 "Index 4" 5 "Index 5" 6 "Index 6" 7 "Index 7" 8 "Index 8" 9 "Index 9" 10 "Index 10" 11 "Index 11" 12 "Index 12" 13 "Index 13" 14 "Index 14" 15 "Index 15" 16 "Index 16" 17 "Index 17" 18 "Index 18" 19 "Index 19" 20 "Index 20" 21 "Index 21" 22 "Index 22" 23 "Index 23" 24 "Index 24" 25 "Index 25" 26 "Index 26" 27 "Index 27" 28 "Index 28" 29 "Index 29" 30 "Index 30" 31 "Index 31" 255 "Null" ;
VAL_ 2467475281 S2M_SBMU_Result_17 0 "默认值" 1 "写入成功" 2 "写入失败" ;
VAL_ 2467475282 S2M_IDX_CMD_Type_18 0 "Invalid" 1 "Request address confirmation" 2 "Reserve" 3 "Sucess" ;
VAL_ 2467475282 S2M_IDX_SBMU_Index_18 0 "Initial Index" 1 "Index 1" 2 "Index 2" 3 "Index 3" 4 "Index 4" 5 "Index 5" 6 "Index 6" 7 "Index 7" 8 "Index 8" 9 "Index 9" 10 "Index 10" 11 "Index 11" 12 "Index 12" 13 "Index 13" 14 "Index 14" 15 "Index 15" 16 "Index 16" 17 "Index 17" 18 "Index 18" 19 "Index 19" 20 "Index 20" 21 "Index 21" 22 "Index 22" 23 "Index 23" 24 "Index 24" 25 "Index 25" 26 "Index 26" 27 "Index 27" 28 "Index 28" 29 "Index 29" 30 "Index 30" 31 "Index 31" 255 "Null" ;
VAL_ 2467475282 S2M_SBMU_Result_18 0 "默认值" 1 "写入成功" 2 "写入失败" ;
VAL_ 2467475283 S2M_IDX_CMD_Type_19 0 "Invalid" 1 "Request address confirmation" 2 "Reserve" 3 "Sucess" ;
VAL_ 2467475283 S2M_IDX_SBMU_Index_19 0 "Initial Index" 1 "Index 1" 2 "Index 2" 3 "Index 3" 4 "Index 4" 5 "Index 5" 6 "Index 6" 7 "Index 7" 8 "Index 8" 9 "Index 9" 10 "Index 10" 11 "Index 11" 12 "Index 12" 13 "Index 13" 14 "Index 14" 15 "Index 15" 16 "Index 16" 17 "Index 17" 18 "Index 18" 19 "Index 19" 20 "Index 20" 21 "Index 21" 22 "Index 22" 23 "Index 23" 24 "Index 24" 25 "Index 25" 26 "Index 26" 27 "Index 27" 28 "Index 28" 29 "Index 29" 30 "Index 30" 31 "Index 31" 255 "Null" ;
VAL_ 2467475283 S2M_SBMU_Result_19 0 "默认值" 1 "写入成功" 2 "写入失败" ;
VAL_ 2467475284 S2M_IDX_CMD_Type_20 0 "Invalid" 1 "Request address confirmation" 2 "Reserve" 3 "Sucess" ;
VAL_ 2467475284 S2M_IDX_SBMU_Index_20 0 "Initial Index" 1 "Index 1" 2 "Index 2" 3 "Index 3" 4 "Index 4" 5 "Index 5" 6 "Index 6" 7 "Index 7" 8 "Index 8" 9 "Index 9" 10 "Index 10" 11 "Index 11" 12 "Index 12" 13 "Index 13" 14 "Index 14" 15 "Index 15" 16 "Index 16" 17 "Index 17" 18 "Index 18" 19 "Index 19" 20 "Index 20" 21 "Index 21" 22 "Index 22" 23 "Index 23" 24 "Index 24" 25 "Index 25" 26 "Index 26" 27 "Index 27" 28 "Index 28" 29 "Index 29" 30 "Index 30" 31 "Index 31" 255 "Null" ;
VAL_ 2467475284 S2M_SBMU_Result_20 0 "默认值" 1 "写入成功" 2 "写入失败" ;
VAL_ 2467475285 S2M_IDX_CMD_Type_21 0 "Invalid" 1 "Request address confirmation" 2 "Reserve" 3 "Sucess" ;
VAL_ 2467475285 S2M_IDX_SBMU_Index_21 0 "Initial Index" 1 "Index 1" 2 "Index 2" 3 "Index 3" 4 "Index 4" 5 "Index 5" 6 "Index 6" 7 "Index 7" 8 "Index 8" 9 "Index 9" 10 "Index 10" 11 "Index 11" 12 "Index 12" 13 "Index 13" 14 "Index 14" 15 "Index 15" 16 "Index 16" 17 "Index 17" 18 "Index 18" 19 "Index 19" 20 "Index 20" 21 "Index 21" 22 "Index 22" 23 "Index 23" 24 "Index 24" 25 "Index 25" 26 "Index 26" 27 "Index 27" 28 "Index 28" 29 "Index 29" 30 "Index 30" 31 "Index 31" 255 "Null" ;
VAL_ 2467475285 S2M_SBMU_Result_21 0 "默认值" 1 "写入成功" 2 "写入失败" ;
VAL_ 2467475286 S2M_IDX_CMD_Type_22 0 "Invalid" 1 "Request address confirmation" 2 "Reserve" 3 "Sucess" ;
VAL_ 2467475286 S2M_IDX_SBMU_Index_22 0 "Initial Index" 1 "Index 1" 2 "Index 2" 3 "Index 3" 4 "Index 4" 5 "Index 5" 6 "Index 6" 7 "Index 7" 8 "Index 8" 9 "Index 9" 10 "Index 10" 11 "Index 11" 12 "Index 12" 13 "Index 13" 14 "Index 14" 15 "Index 15" 16 "Index 16" 17 "Index 17" 18 "Index 18" 19 "Index 19" 20 "Index 20" 21 "Index 21" 22 "Index 22" 23 "Index 23" 24 "Index 24" 25 "Index 25" 26 "Index 26" 27 "Index 27" 28 "Index 28" 29 "Index 29" 30 "Index 30" 31 "Index 31" 255 "Null" ;
VAL_ 2467475286 S2M_SBMU_Result_22 0 "默认值" 1 "写入成功" 2 "写入失败" ;
VAL_ 2467475287 S2M_IDX_CMD_Type_23 0 "Invalid" 1 "Request address confirmation" 2 "Reserve" 3 "Sucess" ;
VAL_ 2467475287 S2M_IDX_SBMU_Index_23 0 "Initial Index" 1 "Index 1" 2 "Index 2" 3 "Index 3" 4 "Index 4" 5 "Index 5" 6 "Index 6" 7 "Index 7" 8 "Index 8" 9 "Index 9" 10 "Index 10" 11 "Index 11" 12 "Index 12" 13 "Index 13" 14 "Index 14" 15 "Index 15" 16 "Index 16" 17 "Index 17" 18 "Index 18" 19 "Index 19" 20 "Index 20" 21 "Index 21" 22 "Index 22" 23 "Index 23" 24 "Index 24" 25 "Index 25" 26 "Index 26" 27 "Index 27" 28 "Index 28" 29 "Index 29" 30 "Index 30" 31 "Index 31" 255 "Null" ;
VAL_ 2467475287 S2M_SBMU_Result_23 0 "默认值" 1 "写入成功" 2 "写入失败" ;
VAL_ 2467475288 S2M_IDX_CMD_Type_24 0 "Invalid" 1 "Request address confirmation" 2 "Reserve" 3 "Sucess" ;
VAL_ 2467475288 S2M_IDX_SBMU_Index_24 0 "Initial Index" 1 "Index 1" 2 "Index 2" 3 "Index 3" 4 "Index 4" 5 "Index 5" 6 "Index 6" 7 "Index 7" 8 "Index 8" 9 "Index 9" 10 "Index 10" 11 "Index 11" 12 "Index 12" 13 "Index 13" 14 "Index 14" 15 "Index 15" 16 "Index 16" 17 "Index 17" 18 "Index 18" 19 "Index 19" 20 "Index 20" 21 "Index 21" 22 "Index 22" 23 "Index 23" 24 "Index 24" 25 "Index 25" 26 "Index 26" 27 "Index 27" 28 "Index 28" 29 "Index 29" 30 "Index 30" 31 "Index 31" 255 "Null" ;
VAL_ 2467475288 S2M_SBMU_Result_24 0 "默认值" 1 "写入成功" 2 "写入失败" ;
VAL_ 2467475289 S2M_IDX_CMD_Type_25 0 "Invalid" 1 "Request address confirmation" 2 "Reserve" 3 "Sucess" ;
VAL_ 2467475289 S2M_IDX_SBMU_Index_25 0 "Initial Index" 1 "Index 1" 2 "Index 2" 3 "Index 3" 4 "Index 4" 5 "Index 5" 6 "Index 6" 7 "Index 7" 8 "Index 8" 9 "Index 9" 10 "Index 10" 11 "Index 11" 12 "Index 12" 13 "Index 13" 14 "Index 14" 15 "Index 15" 16 "Index 16" 17 "Index 17" 18 "Index 18" 19 "Index 19" 20 "Index 20" 21 "Index 21" 22 "Index 22" 23 "Index 23" 24 "Index 24" 25 "Index 25" 26 "Index 26" 27 "Index 27" 28 "Index 28" 29 "Index 29" 30 "Index 30" 31 "Index 31" 255 "Null" ;
VAL_ 2467475289 S2M_SBMU_Result_25 0 "默认值" 1 "写入成功" 2 "写入失败" ;
VAL_ 2467475290 S2M_IDX_CMD_Type_26 0 "Invalid" 1 "Request address confirmation" 2 "Reserve" 3 "Sucess" ;
VAL_ 2467475290 S2M_IDX_SBMU_Index_26 0 "Initial Index" 1 "Index 1" 2 "Index 2" 3 "Index 3" 4 "Index 4" 5 "Index 5" 6 "Index 6" 7 "Index 7" 8 "Index 8" 9 "Index 9" 10 "Index 10" 11 "Index 11" 12 "Index 12" 13 "Index 13" 14 "Index 14" 15 "Index 15" 16 "Index 16" 17 "Index 17" 18 "Index 18" 19 "Index 19" 20 "Index 20" 21 "Index 21" 22 "Index 22" 23 "Index 23" 24 "Index 24" 25 "Index 25" 26 "Index 26" 27 "Index 27" 28 "Index 28" 29 "Index 29" 30 "Index 30" 31 "Index 31" 255 "Null" ;
VAL_ 2467475290 S2M_SBMU_Result_26 0 "默认值" 1 "写入成功" 2 "写入失败" ;
VAL_ 2467475291 S2M_IDX_CMD_Type_27 0 "Invalid" 1 "Request address confirmation" 2 "Reserve" 3 "Sucess" ;
VAL_ 2467475291 S2M_IDX_SBMU_Index_27 0 "Initial Index" 1 "Index 1" 2 "Index 2" 3 "Index 3" 4 "Index 4" 5 "Index 5" 6 "Index 6" 7 "Index 7" 8 "Index 8" 9 "Index 9" 10 "Index 10" 11 "Index 11" 12 "Index 12" 13 "Index 13" 14 "Index 14" 15 "Index 15" 16 "Index 16" 17 "Index 17" 18 "Index 18" 19 "Index 19" 20 "Index 20" 21 "Index 21" 22 "Index 22" 23 "Index 23" 24 "Index 24" 25 "Index 25" 26 "Index 26" 27 "Index 27" 28 "Index 28" 29 "Index 29" 30 "Index 30" 31 "Index 31" 255 "Null" ;
VAL_ 2467475291 S2M_SBMU_Result_27 0 "默认值" 1 "写入成功" 2 "写入失败" ;
VAL_ 2467475292 S2M_IDX_CMD_Type_28 0 "Invalid" 1 "Request address confirmation" 2 "Reserve" 3 "Sucess" ;
VAL_ 2467475292 S2M_IDX_SBMU_Index_28 0 "Initial Index" 1 "Index 1" 2 "Index 2" 3 "Index 3" 4 "Index 4" 5 "Index 5" 6 "Index 6" 7 "Index 7" 8 "Index 8" 9 "Index 9" 10 "Index 10" 11 "Index 11" 12 "Index 12" 13 "Index 13" 14 "Index 14" 15 "Index 15" 16 "Index 16" 17 "Index 17" 18 "Index 18" 19 "Index 19" 20 "Index 20" 21 "Index 21" 22 "Index 22" 23 "Index 23" 24 "Index 24" 25 "Index 25" 26 "Index 26" 27 "Index 27" 28 "Index 28" 29 "Index 29" 30 "Index 30" 31 "Index 31" 255 "Null" ;
VAL_ 2467475292 S2M_SBMU_Result_28 0 "默认值" 1 "写入成功" 2 "写入失败" ;
VAL_ 2467475293 S2M_IDX_CMD_Type_29 0 "Invalid" 1 "Request address confirmation" 2 "Reserve" 3 "Sucess" ;
VAL_ 2467475293 S2M_IDX_SBMU_Index_29 0 "Initial Index" 1 "Index 1" 2 "Index 2" 3 "Index 3" 4 "Index 4" 5 "Index 5" 6 "Index 6" 7 "Index 7" 8 "Index 8" 9 "Index 9" 10 "Index 10" 11 "Index 11" 12 "Index 12" 13 "Index 13" 14 "Index 14" 15 "Index 15" 16 "Index 16" 17 "Index 17" 18 "Index 18" 19 "Index 19" 20 "Index 20" 21 "Index 21" 22 "Index 22" 23 "Index 23" 24 "Index 24" 25 "Index 25" 26 "Index 26" 27 "Index 27" 28 "Index 28" 29 "Index 29" 30 "Index 30" 31 "Index 31" 255 "Null" ;
VAL_ 2467475293 S2M_SBMU_Result_29 0 "默认值" 1 "写入成功" 2 "写入失败" ;
VAL_ 2467475294 S2M_IDX_CMD_Type_30 0 "Invalid" 1 "Request address confirmation" 2 "Reserve" 3 "Sucess" ;
VAL_ 2467475294 S2M_IDX_SBMU_Index_30 0 "Initial Index" 1 "Index 1" 2 "Index 2" 3 "Index 3" 4 "Index 4" 5 "Index 5" 6 "Index 6" 7 "Index 7" 8 "Index 8" 9 "Index 9" 10 "Index 10" 11 "Index 11" 12 "Index 12" 13 "Index 13" 14 "Index 14" 15 "Index 15" 16 "Index 16" 17 "Index 17" 18 "Index 18" 19 "Index 19" 20 "Index 20" 21 "Index 21" 22 "Index 22" 23 "Index 23" 24 "Index 24" 25 "Index 25" 26 "Index 26" 27 "Index 27" 28 "Index 28" 29 "Index 29" 30 "Index 30" 31 "Index 31" 255 "Null" ;
VAL_ 2467475294 S2M_SBMU_Result_30 0 "默认值" 1 "写入成功" 2 "写入失败" ;
VAL_ 2467475295 S2M_IDX_CMD_Type_31 0 "Invalid" 1 "Request address confirmation" 2 "Reserve" 3 "Sucess" ;
VAL_ 2467475295 S2M_IDX_SBMU_Index_31 0 "Initial Index" 1 "Index 1" 2 "Index 2" 3 "Index 3" 4 "Index 4" 5 "Index 5" 6 "Index 6" 7 "Index 7" 8 "Index 8" 9 "Index 9" 10 "Index 10" 11 "Index 11" 12 "Index 12" 13 "Index 13" 14 "Index 14" 15 "Index 15" 16 "Index 16" 17 "Index 17" 18 "Index 18" 19 "Index 19" 20 "Index 20" 21 "Index 21" 22 "Index 22" 23 "Index 23" 24 "Index 24" 25 "Index 25" 26 "Index 26" 27 "Index 27" 28 "Index 28" 29 "Index 29" 30 "Index 30" 31 "Index 31" 255 "Null" ;
VAL_ 2467475295 S2M_SBMU_Result_31 0 "默认值" 1 "写入成功" 2 "写入失败" ;
VAL_ 2467475296 S2M_IDX_CMD_Type_32 0 "Invalid" 1 "Request address confirmation" 2 "Reserve" 3 "Sucess" ;
VAL_ 2467475296 S2M_IDX_SBMU_Index_32 0 "Initial Index" 1 "Index 1" 2 "Index 2" 3 "Index 3" 4 "Index 4" 5 "Index 5" 6 "Index 6" 7 "Index 7" 8 "Index 8" 9 "Index 9" 10 "Index 10" 11 "Index 11" 12 "Index 12" 13 "Index 13" 14 "Index 14" 15 "Index 15" 16 "Index 16" 17 "Index 17" 18 "Index 18" 19 "Index 19" 20 "Index 20" 21 "Index 21" 22 "Index 22" 23 "Index 23" 24 "Index 24" 25 "Index 25" 26 "Index 26" 27 "Index 27" 28 "Index 28" 29 "Index 29" 30 "Index 30" 31 "Index 31" 255 "Null" ;
VAL_ 2467475296 S2M_SBMU_Result_32 0 "默认值" 1 "写入成功" 2 "写入失败" ;
VAL_ 2467475297 S2M_IDX_CMD_Type_33 0 "Invalid" 1 "Request address confirmation" 2 "Reserve" 3 "Sucess" ;
VAL_ 2467475297 S2M_IDX_SBMU_Index_33 0 "Initial Index" 1 "Index 1" 2 "Index 2" 3 "Index 3" 4 "Index 4" 5 "Index 5" 6 "Index 6" 7 "Index 7" 8 "Index 8" 9 "Index 9" 10 "Index 10" 11 "Index 11" 12 "Index 12" 13 "Index 13" 14 "Index 14" 15 "Index 15" 16 "Index 16" 17 "Index 17" 18 "Index 18" 19 "Index 19" 20 "Index 20" 21 "Index 21" 22 "Index 22" 23 "Index 23" 24 "Index 24" 25 "Index 25" 26 "Index 26" 27 "Index 27" 28 "Index 28" 29 "Index 29" 30 "Index 30" 31 "Index 31" 255 "Null" ;
VAL_ 2467475297 S2M_SBMU_Result_33 0 "默认值" 1 "写入成功" 2 "写入失败" ;
VAL_ 2467475298 S2M_IDX_CMD_Type_34 0 "Invalid" 1 "Request address confirmation" 2 "Reserve" 3 "Sucess" ;
VAL_ 2467475298 S2M_IDX_SBMU_Index_34 0 "Initial Index" 1 "Index 1" 2 "Index 2" 3 "Index 3" 4 "Index 4" 5 "Index 5" 6 "Index 6" 7 "Index 7" 8 "Index 8" 9 "Index 9" 10 "Index 10" 11 "Index 11" 12 "Index 12" 13 "Index 13" 14 "Index 14" 15 "Index 15" 16 "Index 16" 17 "Index 17" 18 "Index 18" 19 "Index 19" 20 "Index 20" 21 "Index 21" 22 "Index 22" 23 "Index 23" 24 "Index 24" 25 "Index 25" 26 "Index 26" 27 "Index 27" 28 "Index 28" 29 "Index 29" 30 "Index 30" 31 "Index 31" 255 "Null" ;
VAL_ 2467475298 S2M_SBMU_Result_34 0 "默认值" 1 "写入成功" 2 "写入失败" ;
VAL_ 2467475299 S2M_IDX_CMD_Type_35 0 "Invalid" 1 "Request address confirmation" 2 "Reserve" 3 "Sucess" ;
VAL_ 2467475299 S2M_IDX_SBMU_Index_35 0 "Initial Index" 1 "Index 1" 2 "Index 2" 3 "Index 3" 4 "Index 4" 5 "Index 5" 6 "Index 6" 7 "Index 7" 8 "Index 8" 9 "Index 9" 10 "Index 10" 11 "Index 11" 12 "Index 12" 13 "Index 13" 14 "Index 14" 15 "Index 15" 16 "Index 16" 17 "Index 17" 18 "Index 18" 19 "Index 19" 20 "Index 20" 21 "Index 21" 22 "Index 22" 23 "Index 23" 24 "Index 24" 25 "Index 25" 26 "Index 26" 27 "Index 27" 28 "Index 28" 29 "Index 29" 30 "Index 30" 31 "Index 31" 255 "Null" ;
VAL_ 2467475299 S2M_SBMU_Result_35 0 "默认值" 1 "写入成功" 2 "写入失败" ;
VAL_ 2467475300 S2M_IDX_CMD_Type_36 0 "Invalid" 1 "Request address confirmation" 2 "Reserve" 3 "Sucess" ;
VAL_ 2467475300 S2M_IDX_SBMU_Index_36 0 "Initial Index" 1 "Index 1" 2 "Index 2" 3 "Index 3" 4 "Index 4" 5 "Index 5" 6 "Index 6" 7 "Index 7" 8 "Index 8" 9 "Index 9" 10 "Index 10" 11 "Index 11" 12 "Index 12" 13 "Index 13" 14 "Index 14" 15 "Index 15" 16 "Index 16" 17 "Index 17" 18 "Index 18" 19 "Index 19" 20 "Index 20" 21 "Index 21" 22 "Index 22" 23 "Index 23" 24 "Index 24" 25 "Index 25" 26 "Index 26" 27 "Index 27" 28 "Index 28" 29 "Index 29" 30 "Index 30" 31 "Index 31" 255 "Null" ;
VAL_ 2467475300 S2M_SBMU_Result_36 0 "默认值" 1 "写入成功" 2 "写入失败" ;
VAL_ 2467475301 S2M_IDX_CMD_Type_37 0 "Invalid" 1 "Request address confirmation" 2 "Reserve" 3 "Sucess" ;
VAL_ 2467475301 S2M_IDX_SBMU_Index_37 0 "Initial Index" 1 "Index 1" 2 "Index 2" 3 "Index 3" 4 "Index 4" 5 "Index 5" 6 "Index 6" 7 "Index 7" 8 "Index 8" 9 "Index 9" 10 "Index 10" 11 "Index 11" 12 "Index 12" 13 "Index 13" 14 "Index 14" 15 "Index 15" 16 "Index 16" 17 "Index 17" 18 "Index 18" 19 "Index 19" 20 "Index 20" 21 "Index 21" 22 "Index 22" 23 "Index 23" 24 "Index 24" 25 "Index 25" 26 "Index 26" 27 "Index 27" 28 "Index 28" 29 "Index 29" 30 "Index 30" 31 "Index 31" 255 "Null" ;
VAL_ 2467475301 S2M_SBMU_Result_37 0 "默认值" 1 "写入成功" 2 "写入失败" ;
VAL_ 2467475302 S2M_IDX_CMD_Type_38 0 "Invalid" 1 "Request address confirmation" 2 "Reserve" 3 "Sucess" ;
VAL_ 2467475302 S2M_IDX_SBMU_Index_38 0 "Initial Index" 1 "Index 1" 2 "Index 2" 3 "Index 3" 4 "Index 4" 5 "Index 5" 6 "Index 6" 7 "Index 7" 8 "Index 8" 9 "Index 9" 10 "Index 10" 11 "Index 11" 12 "Index 12" 13 "Index 13" 14 "Index 14" 15 "Index 15" 16 "Index 16" 17 "Index 17" 18 "Index 18" 19 "Index 19" 20 "Index 20" 21 "Index 21" 22 "Index 22" 23 "Index 23" 24 "Index 24" 25 "Index 25" 26 "Index 26" 27 "Index 27" 28 "Index 28" 29 "Index 29" 30 "Index 30" 31 "Index 31" 255 "Null" ;
VAL_ 2467475302 S2M_SBMU_Result_38 0 "默认值" 1 "写入成功" 2 "写入失败" ;
VAL_ 2467475303 S2M_IDX_CMD_Type_39 0 "Invalid" 1 "Request address confirmation" 2 "Reserve" 3 "Sucess" ;
VAL_ 2467475303 S2M_IDX_SBMU_Index_39 0 "Initial Index" 1 "Index 1" 2 "Index 2" 3 "Index 3" 4 "Index 4" 5 "Index 5" 6 "Index 6" 7 "Index 7" 8 "Index 8" 9 "Index 9" 10 "Index 10" 11 "Index 11" 12 "Index 12" 13 "Index 13" 14 "Index 14" 15 "Index 15" 16 "Index 16" 17 "Index 17" 18 "Index 18" 19 "Index 19" 20 "Index 20" 21 "Index 21" 22 "Index 22" 23 "Index 23" 24 "Index 24" 25 "Index 25" 26 "Index 26" 27 "Index 27" 28 "Index 28" 29 "Index 29" 30 "Index 30" 31 "Index 31" 255 "Null" ;
VAL_ 2467475303 S2M_SBMU_Result_39 0 "默认值" 1 "写入成功" 2 "写入失败" ;
VAL_ 2467475304 S2M_IDX_CMD_Type_40 0 "Invalid" 1 "Request address confirmation" 2 "Reserve" 3 "Sucess" ;
VAL_ 2467475304 S2M_IDX_SBMU_Index_40 0 "Initial Index" 1 "Index 1" 2 "Index 2" 3 "Index 3" 4 "Index 4" 5 "Index 5" 6 "Index 6" 7 "Index 7" 8 "Index 8" 9 "Index 9" 10 "Index 10" 11 "Index 11" 12 "Index 12" 13 "Index 13" 14 "Index 14" 15 "Index 15" 16 "Index 16" 17 "Index 17" 18 "Index 18" 19 "Index 19" 20 "Index 20" 21 "Index 21" 22 "Index 22" 23 "Index 23" 24 "Index 24" 25 "Index 25" 26 "Index 26" 27 "Index 27" 28 "Index 28" 29 "Index 29" 30 "Index 30" 31 "Index 31" 255 "Null" ;
VAL_ 2467475304 S2M_SBMU_Result_40 0 "默认值" 1 "写入成功" 2 "写入失败" ;
VAL_ 2467475305 S2M_IDX_CMD_Type_41 0 "Invalid" 1 "Request address confirmation" 2 "Reserve" 3 "Sucess" ;
VAL_ 2467475305 S2M_IDX_SBMU_Index_41 0 "Initial Index" 1 "Index 1" 2 "Index 2" 3 "Index 3" 4 "Index 4" 5 "Index 5" 6 "Index 6" 7 "Index 7" 8 "Index 8" 9 "Index 9" 10 "Index 10" 11 "Index 11" 12 "Index 12" 13 "Index 13" 14 "Index 14" 15 "Index 15" 16 "Index 16" 17 "Index 17" 18 "Index 18" 19 "Index 19" 20 "Index 20" 21 "Index 21" 22 "Index 22" 23 "Index 23" 24 "Index 24" 25 "Index 25" 26 "Index 26" 27 "Index 27" 28 "Index 28" 29 "Index 29" 30 "Index 30" 31 "Index 31" 255 "Null" ;
VAL_ 2467475305 S2M_SBMU_Result_41 0 "默认值" 1 "写入成功" 2 "写入失败" ;
VAL_ 2467475306 S2M_IDX_CMD_Type_42 0 "Invalid" 1 "Request address confirmation" 2 "Reserve" 3 "Sucess" ;
VAL_ 2467475306 S2M_IDX_SBMU_Index_42 0 "Initial Index" 1 "Index 1" 2 "Index 2" 3 "Index 3" 4 "Index 4" 5 "Index 5" 6 "Index 6" 7 "Index 7" 8 "Index 8" 9 "Index 9" 10 "Index 10" 11 "Index 11" 12 "Index 12" 13 "Index 13" 14 "Index 14" 15 "Index 15" 16 "Index 16" 17 "Index 17" 18 "Index 18" 19 "Index 19" 20 "Index 20" 21 "Index 21" 22 "Index 22" 23 "Index 23" 24 "Index 24" 25 "Index 25" 26 "Index 26" 27 "Index 27" 28 "Index 28" 29 "Index 29" 30 "Index 30" 31 "Index 31" 255 "Null" ;
VAL_ 2467475306 S2M_SBMU_Result_42 0 "默认值" 1 "写入成功" 2 "写入失败" ;
VAL_ 2467475307 S2M_IDX_CMD_Type_43 0 "Invalid" 1 "Request address confirmation" 2 "Reserve" 3 "Sucess" ;
VAL_ 2467475307 S2M_IDX_SBMU_Index_43 0 "Initial Index" 1 "Index 1" 2 "Index 2" 3 "Index 3" 4 "Index 4" 5 "Index 5" 6 "Index 6" 7 "Index 7" 8 "Index 8" 9 "Index 9" 10 "Index 10" 11 "Index 11" 12 "Index 12" 13 "Index 13" 14 "Index 14" 15 "Index 15" 16 "Index 16" 17 "Index 17" 18 "Index 18" 19 "Index 19" 20 "Index 20" 21 "Index 21" 22 "Index 22" 23 "Index 23" 24 "Index 24" 25 "Index 25" 26 "Index 26" 27 "Index 27" 28 "Index 28" 29 "Index 29" 30 "Index 30" 31 "Index 31" 255 "Null" ;
VAL_ 2467475307 S2M_SBMU_Result_43 0 "默认值" 1 "写入成功" 2 "写入失败" ;
VAL_ 2467475308 S2M_IDX_CMD_Type_44 0 "Invalid" 1 "Request address confirmation" 2 "Reserve" 3 "Sucess" ;
VAL_ 2467475308 S2M_IDX_SBMU_Index_44 0 "Initial Index" 1 "Index 1" 2 "Index 2" 3 "Index 3" 4 "Index 4" 5 "Index 5" 6 "Index 6" 7 "Index 7" 8 "Index 8" 9 "Index 9" 10 "Index 10" 11 "Index 11" 12 "Index 12" 13 "Index 13" 14 "Index 14" 15 "Index 15" 16 "Index 16" 17 "Index 17" 18 "Index 18" 19 "Index 19" 20 "Index 20" 21 "Index 21" 22 "Index 22" 23 "Index 23" 24 "Index 24" 25 "Index 25" 26 "Index 26" 27 "Index 27" 28 "Index 28" 29 "Index 29" 30 "Index 30" 31 "Index 31" 255 "Null" ;
VAL_ 2467475308 S2M_SBMU_Result_44 0 "默认值" 1 "写入成功" 2 "写入失败" ;
VAL_ 2467475309 S2M_IDX_CMD_Type_45 0 "Invalid" 1 "Request address confirmation" 2 "Reserve" 3 "Sucess" ;
VAL_ 2467475309 S2M_IDX_SBMU_Index_45 0 "Initial Index" 1 "Index 1" 2 "Index 2" 3 "Index 3" 4 "Index 4" 5 "Index 5" 6 "Index 6" 7 "Index 7" 8 "Index 8" 9 "Index 9" 10 "Index 10" 11 "Index 11" 12 "Index 12" 13 "Index 13" 14 "Index 14" 15 "Index 15" 16 "Index 16" 17 "Index 17" 18 "Index 18" 19 "Index 19" 20 "Index 20" 21 "Index 21" 22 "Index 22" 23 "Index 23" 24 "Index 24" 25 "Index 25" 26 "Index 26" 27 "Index 27" 28 "Index 28" 29 "Index 29" 30 "Index 30" 31 "Index 31" 255 "Null" ;
VAL_ 2467475309 S2M_SBMU_Result_45 0 "默认值" 1 "写入成功" 2 "写入失败" ;
VAL_ 2467475310 S2M_IDX_CMD_Type_46 0 "Invalid" 1 "Request address confirmation" 2 "Reserve" 3 "Sucess" ;
VAL_ 2467475310 S2M_IDX_SBMU_Index_46 0 "Initial Index" 1 "Index 1" 2 "Index 2" 3 "Index 3" 4 "Index 4" 5 "Index 5" 6 "Index 6" 7 "Index 7" 8 "Index 8" 9 "Index 9" 10 "Index 10" 11 "Index 11" 12 "Index 12" 13 "Index 13" 14 "Index 14" 15 "Index 15" 16 "Index 16" 17 "Index 17" 18 "Index 18" 19 "Index 19" 20 "Index 20" 21 "Index 21" 22 "Index 22" 23 "Index 23" 24 "Index 24" 25 "Index 25" 26 "Index 26" 27 "Index 27" 28 "Index 28" 29 "Index 29" 30 "Index 30" 31 "Index 31" 255 "Null" ;
VAL_ 2467475310 S2M_SBMU_Result_46 0 "默认值" 1 "写入成功" 2 "写入失败" ;
VAL_ 2467475311 S2M_IDX_CMD_Type_47 0 "Invalid" 1 "Request address confirmation" 2 "Reserve" 3 "Sucess" ;
VAL_ 2467475311 S2M_IDX_SBMU_Index_47 0 "Initial Index" 1 "Index 1" 2 "Index 2" 3 "Index 3" 4 "Index 4" 5 "Index 5" 6 "Index 6" 7 "Index 7" 8 "Index 8" 9 "Index 9" 10 "Index 10" 11 "Index 11" 12 "Index 12" 13 "Index 13" 14 "Index 14" 15 "Index 15" 16 "Index 16" 17 "Index 17" 18 "Index 18" 19 "Index 19" 20 "Index 20" 21 "Index 21" 22 "Index 22" 23 "Index 23" 24 "Index 24" 25 "Index 25" 26 "Index 26" 27 "Index 27" 28 "Index 28" 29 "Index 29" 30 "Index 30" 31 "Index 31" 255 "Null" ;
VAL_ 2467475311 S2M_SBMU_Result_47 0 "默认值" 1 "写入成功" 2 "写入失败" ;
VAL_ 2467475312 S2M_IDX_CMD_Type_48 0 "Invalid" 1 "Request address confirmation" 2 "Reserve" 3 "Sucess" ;
VAL_ 2467475312 S2M_IDX_SBMU_Index_48 0 "Initial Index" 1 "Index 1" 2 "Index 2" 3 "Index 3" 4 "Index 4" 5 "Index 5" 6 "Index 6" 7 "Index 7" 8 "Index 8" 9 "Index 9" 10 "Index 10" 11 "Index 11" 12 "Index 12" 13 "Index 13" 14 "Index 14" 15 "Index 15" 16 "Index 16" 17 "Index 17" 18 "Index 18" 19 "Index 19" 20 "Index 20" 21 "Index 21" 22 "Index 22" 23 "Index 23" 24 "Index 24" 25 "Index 25" 26 "Index 26" 27 "Index 27" 28 "Index 28" 29 "Index 29" 30 "Index 30" 31 "Index 31" 255 "Null" ;
VAL_ 2467475312 S2M_SBMU_Result_48 0 "默认值" 1 "写入成功" 2 "写入失败" ;
VAL_ 2467475313 S2M_IDX_CMD_Type_49 0 "Invalid" 1 "Request address confirmation" 2 "Reserve" 3 "Sucess" ;
VAL_ 2467475313 S2M_IDX_SBMU_Index_49 0 "Initial Index" 1 "Index 1" 2 "Index 2" 3 "Index 3" 4 "Index 4" 5 "Index 5" 6 "Index 6" 7 "Index 7" 8 "Index 8" 9 "Index 9" 10 "Index 10" 11 "Index 11" 12 "Index 12" 13 "Index 13" 14 "Index 14" 15 "Index 15" 16 "Index 16" 17 "Index 17" 18 "Index 18" 19 "Index 19" 20 "Index 20" 21 "Index 21" 22 "Index 22" 23 "Index 23" 24 "Index 24" 25 "Index 25" 26 "Index 26" 27 "Index 27" 28 "Index 28" 29 "Index 29" 30 "Index 30" 31 "Index 31" 255 "Null" ;
VAL_ 2467475313 S2M_SBMU_Result_49 0 "默认值" 1 "写入成功" 2 "写入失败" ;
VAL_ 2467475314 S2M_IDX_CMD_Type_50 0 "Invalid" 1 "Request address confirmation" 2 "Reserve" 3 "Sucess" ;
VAL_ 2467475314 S2M_IDX_SBMU_Index_50 0 "Initial Index" 1 "Index 1" 2 "Index 2" 3 "Index 3" 4 "Index 4" 5 "Index 5" 6 "Index 6" 7 "Index 7" 8 "Index 8" 9 "Index 9" 10 "Index 10" 11 "Index 11" 12 "Index 12" 13 "Index 13" 14 "Index 14" 15 "Index 15" 16 "Index 16" 17 "Index 17" 18 "Index 18" 19 "Index 19" 20 "Index 20" 21 "Index 21" 22 "Index 22" 23 "Index 23" 24 "Index 24" 25 "Index 25" 26 "Index 26" 27 "Index 27" 28 "Index 28" 29 "Index 29" 30 "Index 30" 31 "Index 31" 255 "Null" ;
VAL_ 2467475314 S2M_SBMU_Result_50 0 "默认值" 1 "写入成功" 2 "写入失败" ;
VAL_ 2467475315 S2M_IDX_CMD_Type_51 0 "Invalid" 1 "Request address confirmation" 2 "Reserve" 3 "Sucess" ;
VAL_ 2467475315 S2M_IDX_SBMU_Index_51 0 "Initial Index" 1 "Index 1" 2 "Index 2" 3 "Index 3" 4 "Index 4" 5 "Index 5" 6 "Index 6" 7 "Index 7" 8 "Index 8" 9 "Index 9" 10 "Index 10" 11 "Index 11" 12 "Index 12" 13 "Index 13" 14 "Index 14" 15 "Index 15" 16 "Index 16" 17 "Index 17" 18 "Index 18" 19 "Index 19" 20 "Index 20" 21 "Index 21" 22 "Index 22" 23 "Index 23" 24 "Index 24" 25 "Index 25" 26 "Index 26" 27 "Index 27" 28 "Index 28" 29 "Index 29" 30 "Index 30" 31 "Index 31" 255 "Null" ;
VAL_ 2467475315 S2M_SBMU_Result_51 0 "默认值" 1 "写入成功" 2 "写入失败" ;
VAL_ 2467475316 S2M_IDX_CMD_Type_52 0 "Invalid" 1 "Request address confirmation" 2 "Reserve" 3 "Sucess" ;
VAL_ 2467475316 S2M_IDX_SBMU_Index_52 0 "Initial Index" 1 "Index 1" 2 "Index 2" 3 "Index 3" 4 "Index 4" 5 "Index 5" 6 "Index 6" 7 "Index 7" 8 "Index 8" 9 "Index 9" 10 "Index 10" 11 "Index 11" 12 "Index 12" 13 "Index 13" 14 "Index 14" 15 "Index 15" 16 "Index 16" 17 "Index 17" 18 "Index 18" 19 "Index 19" 20 "Index 20" 21 "Index 21" 22 "Index 22" 23 "Index 23" 24 "Index 24" 25 "Index 25" 26 "Index 26" 27 "Index 27" 28 "Index 28" 29 "Index 29" 30 "Index 30" 31 "Index 31" 255 "Null" ;
VAL_ 2467475316 S2M_SBMU_Result_52 0 "默认值" 1 "写入成功" 2 "写入失败" ;
VAL_ 2467475317 S2M_IDX_CMD_Type_53 0 "Invalid" 1 "Request address confirmation" 2 "Reserve" 3 "Sucess" ;
VAL_ 2467475317 S2M_IDX_SBMU_Index_53 0 "Initial Index" 1 "Index 1" 2 "Index 2" 3 "Index 3" 4 "Index 4" 5 "Index 5" 6 "Index 6" 7 "Index 7" 8 "Index 8" 9 "Index 9" 10 "Index 10" 11 "Index 11" 12 "Index 12" 13 "Index 13" 14 "Index 14" 15 "Index 15" 16 "Index 16" 17 "Index 17" 18 "Index 18" 19 "Index 19" 20 "Index 20" 21 "Index 21" 22 "Index 22" 23 "Index 23" 24 "Index 24" 25 "Index 25" 26 "Index 26" 27 "Index 27" 28 "Index 28" 29 "Index 29" 30 "Index 30" 31 "Index 31" 255 "Null" ;
VAL_ 2467475317 S2M_SBMU_Result_53 0 "默认值" 1 "写入成功" 2 "写入失败" ;
VAL_ 2467475318 S2M_IDX_CMD_Type_54 0 "Invalid" 1 "Request address confirmation" 2 "Reserve" 3 "Sucess" ;
VAL_ 2467475318 S2M_IDX_SBMU_Index_54 0 "Initial Index" 1 "Index 1" 2 "Index 2" 3 "Index 3" 4 "Index 4" 5 "Index 5" 6 "Index 6" 7 "Index 7" 8 "Index 8" 9 "Index 9" 10 "Index 10" 11 "Index 11" 12 "Index 12" 13 "Index 13" 14 "Index 14" 15 "Index 15" 16 "Index 16" 17 "Index 17" 18 "Index 18" 19 "Index 19" 20 "Index 20" 21 "Index 21" 22 "Index 22" 23 "Index 23" 24 "Index 24" 25 "Index 25" 26 "Index 26" 27 "Index 27" 28 "Index 28" 29 "Index 29" 30 "Index 30" 31 "Index 31" 255 "Null" ;
VAL_ 2467475318 S2M_SBMU_Result_54 0 "默认值" 1 "写入成功" 2 "写入失败" ;
VAL_ 2467475319 S2M_IDX_CMD_Type_55 0 "Invalid" 1 "Request address confirmation" 2 "Reserve" 3 "Sucess" ;
VAL_ 2467475319 S2M_IDX_SBMU_Index_55 0 "Initial Index" 1 "Index 1" 2 "Index 2" 3 "Index 3" 4 "Index 4" 5 "Index 5" 6 "Index 6" 7 "Index 7" 8 "Index 8" 9 "Index 9" 10 "Index 10" 11 "Index 11" 12 "Index 12" 13 "Index 13" 14 "Index 14" 15 "Index 15" 16 "Index 16" 17 "Index 17" 18 "Index 18" 19 "Index 19" 20 "Index 20" 21 "Index 21" 22 "Index 22" 23 "Index 23" 24 "Index 24" 25 "Index 25" 26 "Index 26" 27 "Index 27" 28 "Index 28" 29 "Index 29" 30 "Index 30" 31 "Index 31" 255 "Null" ;
VAL_ 2467475319 S2M_SBMU_Result_55 0 "默认值" 1 "写入成功" 2 "写入失败" ;
VAL_ 2467475320 S2M_IDX_CMD_Type_56 0 "Invalid" 1 "Request address confirmation" 2 "Reserve" 3 "Sucess" ;
VAL_ 2467475320 S2M_IDX_SBMU_Index_56 0 "Initial Index" 1 "Index 1" 2 "Index 2" 3 "Index 3" 4 "Index 4" 5 "Index 5" 6 "Index 6" 7 "Index 7" 8 "Index 8" 9 "Index 9" 10 "Index 10" 11 "Index 11" 12 "Index 12" 13 "Index 13" 14 "Index 14" 15 "Index 15" 16 "Index 16" 17 "Index 17" 18 "Index 18" 19 "Index 19" 20 "Index 20" 21 "Index 21" 22 "Index 22" 23 "Index 23" 24 "Index 24" 25 "Index 25" 26 "Index 26" 27 "Index 27" 28 "Index 28" 29 "Index 29" 30 "Index 30" 31 "Index 31" 255 "Null" ;
VAL_ 2467475320 S2M_SBMU_Result_56 0 "默认值" 1 "写入成功" 2 "写入失败" ;
VAL_ 2467475321 S2M_IDX_CMD_Type_57 0 "Invalid" 1 "Request address confirmation" 2 "Reserve" 3 "Sucess" ;
VAL_ 2467475321 S2M_IDX_SBMU_Index_57 0 "Initial Index" 1 "Index 1" 2 "Index 2" 3 "Index 3" 4 "Index 4" 5 "Index 5" 6 "Index 6" 7 "Index 7" 8 "Index 8" 9 "Index 9" 10 "Index 10" 11 "Index 11" 12 "Index 12" 13 "Index 13" 14 "Index 14" 15 "Index 15" 16 "Index 16" 17 "Index 17" 18 "Index 18" 19 "Index 19" 20 "Index 20" 21 "Index 21" 22 "Index 22" 23 "Index 23" 24 "Index 24" 25 "Index 25" 26 "Index 26" 27 "Index 27" 28 "Index 28" 29 "Index 29" 30 "Index 30" 31 "Index 31" 255 "Null" ;
VAL_ 2467475321 S2M_SBMU_Result_57 0 "默认值" 1 "写入成功" 2 "写入失败" ;
VAL_ 2467475322 S2M_IDX_CMD_Type_58 0 "Invalid" 1 "Request address confirmation" 2 "Reserve" 3 "Sucess" ;
VAL_ 2467475322 S2M_IDX_SBMU_Index_58 0 "Initial Index" 1 "Index 1" 2 "Index 2" 3 "Index 3" 4 "Index 4" 5 "Index 5" 6 "Index 6" 7 "Index 7" 8 "Index 8" 9 "Index 9" 10 "Index 10" 11 "Index 11" 12 "Index 12" 13 "Index 13" 14 "Index 14" 15 "Index 15" 16 "Index 16" 17 "Index 17" 18 "Index 18" 19 "Index 19" 20 "Index 20" 21 "Index 21" 22 "Index 22" 23 "Index 23" 24 "Index 24" 25 "Index 25" 26 "Index 26" 27 "Index 27" 28 "Index 28" 29 "Index 29" 30 "Index 30" 31 "Index 31" 255 "Null" ;
VAL_ 2467475322 S2M_SBMU_Result_58 0 "默认值" 1 "写入成功" 2 "写入失败" ;
VAL_ 2467475323 S2M_IDX_CMD_Type_59 0 "Invalid" 1 "Request address confirmation" 2 "Reserve" 3 "Sucess" ;
VAL_ 2467475323 S2M_IDX_SBMU_Index_59 0 "Initial Index" 1 "Index 1" 2 "Index 2" 3 "Index 3" 4 "Index 4" 5 "Index 5" 6 "Index 6" 7 "Index 7" 8 "Index 8" 9 "Index 9" 10 "Index 10" 11 "Index 11" 12 "Index 12" 13 "Index 13" 14 "Index 14" 15 "Index 15" 16 "Index 16" 17 "Index 17" 18 "Index 18" 19 "Index 19" 20 "Index 20" 21 "Index 21" 22 "Index 22" 23 "Index 23" 24 "Index 24" 25 "Index 25" 26 "Index 26" 27 "Index 27" 28 "Index 28" 29 "Index 29" 30 "Index 30" 31 "Index 31" 255 "Null" ;
VAL_ 2467475323 S2M_SBMU_Result_59 0 "默认值" 1 "写入成功" 2 "写入失败" ;
VAL_ 2467475324 S2M_IDX_CMD_Type_60 0 "Invalid" 1 "Request address confirmation" 2 "Reserve" 3 "Sucess" ;
VAL_ 2467475324 S2M_IDX_SBMU_Index_60 0 "Initial Index" 1 "Index 1" 2 "Index 2" 3 "Index 3" 4 "Index 4" 5 "Index 5" 6 "Index 6" 7 "Index 7" 8 "Index 8" 9 "Index 9" 10 "Index 10" 11 "Index 11" 12 "Index 12" 13 "Index 13" 14 "Index 14" 15 "Index 15" 16 "Index 16" 17 "Index 17" 18 "Index 18" 19 "Index 19" 20 "Index 20" 21 "Index 21" 22 "Index 22" 23 "Index 23" 24 "Index 24" 25 "Index 25" 26 "Index 26" 27 "Index 27" 28 "Index 28" 29 "Index 29" 30 "Index 30" 31 "Index 31" 255 "Null" ;
VAL_ 2467475324 S2M_SBMU_Result_60 0 "默认值" 1 "写入成功" 2 "写入失败" ;
VAL_ 2467475325 S2M_IDX_CMD_Type_61 0 "Invalid" 1 "Request address confirmation" 2 "Reserve" 3 "Sucess" ;
VAL_ 2467475325 S2M_IDX_SBMU_Index_61 0 "Initial Index" 1 "Index 1" 2 "Index 2" 3 "Index 3" 4 "Index 4" 5 "Index 5" 6 "Index 6" 7 "Index 7" 8 "Index 8" 9 "Index 9" 10 "Index 10" 11 "Index 11" 12 "Index 12" 13 "Index 13" 14 "Index 14" 15 "Index 15" 16 "Index 16" 17 "Index 17" 18 "Index 18" 19 "Index 19" 20 "Index 20" 21 "Index 21" 22 "Index 22" 23 "Index 23" 24 "Index 24" 25 "Index 25" 26 "Index 26" 27 "Index 27" 28 "Index 28" 29 "Index 29" 30 "Index 30" 31 "Index 31" 255 "Null" ;
VAL_ 2467475325 S2M_SBMU_Result_61 0 "默认值" 1 "写入成功" 2 "写入失败" ;
VAL_ 2467475326 S2M_IDX_CMD_Type_62 0 "Invalid" 1 "Request address confirmation" 2 "Reserve" 3 "Sucess" ;
VAL_ 2467475326 S2M_IDX_SBMU_Index_62 0 "Initial Index" 1 "Index 1" 2 "Index 2" 3 "Index 3" 4 "Index 4" 5 "Index 5" 6 "Index 6" 7 "Index 7" 8 "Index 8" 9 "Index 9" 10 "Index 10" 11 "Index 11" 12 "Index 12" 13 "Index 13" 14 "Index 14" 15 "Index 15" 16 "Index 16" 17 "Index 17" 18 "Index 18" 19 "Index 19" 20 "Index 20" 21 "Index 21" 22 "Index 22" 23 "Index 23" 24 "Index 24" 25 "Index 25" 26 "Index 26" 27 "Index 27" 28 "Index 28" 29 "Index 29" 30 "Index 30" 31 "Index 31" 255 "Null" ;
VAL_ 2467475326 S2M_SBMU_Result_62 0 "默认值" 1 "写入成功" 2 "写入失败" ;
VAL_ 2467475327 S2M_IDX_CMD_Type_63 0 "Invalid" 1 "Request address confirmation" 2 "Reserve" 3 "Sucess" ;
VAL_ 2467475327 S2M_IDX_SBMU_Index_63 0 "Initial Index" 1 "Index 1" 2 "Index 2" 3 "Index 3" 4 "Index 4" 5 "Index 5" 6 "Index 6" 7 "Index 7" 8 "Index 8" 9 "Index 9" 10 "Index 10" 11 "Index 11" 12 "Index 12" 13 "Index 13" 14 "Index 14" 15 "Index 15" 16 "Index 16" 17 "Index 17" 18 "Index 18" 19 "Index 19" 20 "Index 20" 21 "Index 21" 22 "Index 22" 23 "Index 23" 24 "Index 24" 25 "Index 25" 26 "Index 26" 27 "Index 27" 28 "Index 28" 29 "Index 29" 30 "Index 30" 31 "Index 31" 255 "Null" ;
VAL_ 2467475327 S2M_SBMU_Result_63 0 "默认值" 1 "写入成功" 2 "写入失败" ;
VAL_ 2467540801 D2M_IDX_CMD_Type_01 0 "Invalid" 1 "Request address confirmation" 2 "Coding address" 3 "Not used" 4 "Not used" 5 "Confirm address" 6 "Exit coding" 7 "Enter coding" ;
VAL_ 2467540801 D2M_IDX_DCDC_Index_01 0 "Initial Index" 1 "Index 1" 2 "Index 2" 3 "Index 3" 4 "Index 4" 5 "Index 5" 6 "Index 6" 7 "Index 7" 8 "Index 8" 9 "Index 9" 10 "Index 10" 11 "Index 11" 12 "Index 12" 13 "Index 13" 14 "Index 14" 15 "Index 15" 16 "Index 16" 17 "Index 17" 18 "Index 18" 19 "Index 19" 20 "Index 20" 21 "Index 21" 22 "Index 22" 23 "Index 23" 24 "Index 24" 25 "Index 25" 26 "Index 26" 27 "Index 27" 28 "Index 28" 29 "Index 29" 30 "Index 30" 31 "Index 31" 255 "Null" ;
VAL_ 2467540802 D2M_IDX_CMD_Type_02 0 "Invalid" 1 "Request address confirmation" 2 "Coding address" 3 "Not used" 4 "Not used" 5 "Confirm address" 6 "Exit coding" 7 "Enter coding" ;
VAL_ 2467540802 D2M_IDX_DCDC_Index_02 0 "Initial Index" 1 "Index 1" 2 "Index 2" 3 "Index 3" 4 "Index 4" 5 "Index 5" 6 "Index 6" 7 "Index 7" 8 "Index 8" 9 "Index 9" 10 "Index 10" 11 "Index 11" 12 "Index 12" 13 "Index 13" 14 "Index 14" 15 "Index 15" 16 "Index 16" 17 "Index 17" 18 "Index 18" 19 "Index 19" 20 "Index 20" 21 "Index 21" 22 "Index 22" 23 "Index 23" 24 "Index 24" 25 "Index 25" 26 "Index 26" 27 "Index 27" 28 "Index 28" 29 "Index 29" 30 "Index 30" 31 "Index 31" 255 "Null" ;
VAL_ 2467540803 D2M_IDX_CMD_Type_03 0 "Invalid" 1 "Request address confirmation" 2 "Coding address" 3 "Not used" 4 "Not used" 5 "Confirm address" 6 "Exit coding" 7 "Enter coding" ;
VAL_ 2467540803 D2M_IDX_DCDC_Index_03 0 "Initial Index" 1 "Index 1" 2 "Index 2" 3 "Index 3" 4 "Index 4" 5 "Index 5" 6 "Index 6" 7 "Index 7" 8 "Index 8" 9 "Index 9" 10 "Index 10" 11 "Index 11" 12 "Index 12" 13 "Index 13" 14 "Index 14" 15 "Index 15" 16 "Index 16" 17 "Index 17" 18 "Index 18" 19 "Index 19" 20 "Index 20" 21 "Index 21" 22 "Index 22" 23 "Index 23" 24 "Index 24" 25 "Index 25" 26 "Index 26" 27 "Index 27" 28 "Index 28" 29 "Index 29" 30 "Index 30" 31 "Index 31" 255 "Null" ;
VAL_ 2467540804 D2M_IDX_CMD_Type_04 0 "Invalid" 1 "Request address confirmation" 2 "Coding address" 3 "Not used" 4 "Not used" 5 "Confirm address" 6 "Exit coding" 7 "Enter coding" ;
VAL_ 2467540804 D2M_IDX_DCDC_Index_04 0 "Initial Index" 1 "Index 1" 2 "Index 2" 3 "Index 3" 4 "Index 4" 5 "Index 5" 6 "Index 6" 7 "Index 7" 8 "Index 8" 9 "Index 9" 10 "Index 10" 11 "Index 11" 12 "Index 12" 13 "Index 13" 14 "Index 14" 15 "Index 15" 16 "Index 16" 17 "Index 17" 18 "Index 18" 19 "Index 19" 20 "Index 20" 21 "Index 21" 22 "Index 22" 23 "Index 23" 24 "Index 24" 25 "Index 25" 26 "Index 26" 27 "Index 27" 28 "Index 28" 29 "Index 29" 30 "Index 30" 31 "Index 31" 255 "Null" ;
VAL_ 2467540805 D2M_IDX_CMD_Type_05 0 "Invalid" 1 "Request address confirmation" 2 "Coding address" 3 "Not used" 4 "Not used" 5 "Confirm address" 6 "Exit coding" 7 "Enter coding" ;
VAL_ 2467540805 D2M_IDX_DCDC_Index_05 0 "Initial Index" 1 "Index 1" 2 "Index 2" 3 "Index 3" 4 "Index 4" 5 "Index 5" 6 "Index 6" 7 "Index 7" 8 "Index 8" 9 "Index 9" 10 "Index 10" 11 "Index 11" 12 "Index 12" 13 "Index 13" 14 "Index 14" 15 "Index 15" 16 "Index 16" 17 "Index 17" 18 "Index 18" 19 "Index 19" 20 "Index 20" 21 "Index 21" 22 "Index 22" 23 "Index 23" 24 "Index 24" 25 "Index 25" 26 "Index 26" 27 "Index 27" 28 "Index 28" 29 "Index 29" 30 "Index 30" 31 "Index 31" 255 "Null" ;
VAL_ 2467540806 D2M_IDX_CMD_Type_06 0 "Invalid" 1 "Request address confirmation" 2 "Coding address" 3 "Not used" 4 "Not used" 5 "Confirm address" 6 "Exit coding" 7 "Enter coding" ;
VAL_ 2467540806 D2M_IDX_DCDC_Index_06 0 "Initial Index" 1 "Index 1" 2 "Index 2" 3 "Index 3" 4 "Index 4" 5 "Index 5" 6 "Index 6" 7 "Index 7" 8 "Index 8" 9 "Index 9" 10 "Index 10" 11 "Index 11" 12 "Index 12" 13 "Index 13" 14 "Index 14" 15 "Index 15" 16 "Index 16" 17 "Index 17" 18 "Index 18" 19 "Index 19" 20 "Index 20" 21 "Index 21" 22 "Index 22" 23 "Index 23" 24 "Index 24" 25 "Index 25" 26 "Index 26" 27 "Index 27" 28 "Index 28" 29 "Index 29" 30 "Index 30" 31 "Index 31" 255 "Null" ;
VAL_ 2467540807 D2M_IDX_CMD_Type_07 0 "Invalid" 1 "Request address confirmation" 2 "Coding address" 3 "Not used" 4 "Not used" 5 "Confirm address" 6 "Exit coding" 7 "Enter coding" ;
VAL_ 2467540807 D2M_IDX_DCDC_Index_07 0 "Initial Index" 1 "Index 1" 2 "Index 2" 3 "Index 3" 4 "Index 4" 5 "Index 5" 6 "Index 6" 7 "Index 7" 8 "Index 8" 9 "Index 9" 10 "Index 10" 11 "Index 11" 12 "Index 12" 13 "Index 13" 14 "Index 14" 15 "Index 15" 16 "Index 16" 17 "Index 17" 18 "Index 18" 19 "Index 19" 20 "Index 20" 21 "Index 21" 22 "Index 22" 23 "Index 23" 24 "Index 24" 25 "Index 25" 26 "Index 26" 27 "Index 27" 28 "Index 28" 29 "Index 29" 30 "Index 30" 31 "Index 31" 255 "Null" ;
VAL_ 2467540808 D2M_IDX_CMD_Type_08 0 "Invalid" 1 "Request address confirmation" 2 "Coding address" 3 "Not used" 4 "Not used" 5 "Confirm address" 6 "Exit coding" 7 "Enter coding" ;
VAL_ 2467540808 D2M_IDX_DCDC_Index_08 0 "Initial Index" 1 "Index 1" 2 "Index 2" 3 "Index 3" 4 "Index 4" 5 "Index 5" 6 "Index 6" 7 "Index 7" 8 "Index 8" 9 "Index 9" 10 "Index 10" 11 "Index 11" 12 "Index 12" 13 "Index 13" 14 "Index 14" 15 "Index 15" 16 "Index 16" 17 "Index 17" 18 "Index 18" 19 "Index 19" 20 "Index 20" 21 "Index 21" 22 "Index 22" 23 "Index 23" 24 "Index 24" 25 "Index 25" 26 "Index 26" 27 "Index 27" 28 "Index 28" 29 "Index 29" 30 "Index 30" 31 "Index 31" 255 "Null" ;
VAL_ 2467540809 D2M_IDX_CMD_Type_09 0 "Invalid" 1 "Request address confirmation" 2 "Coding address" 3 "Not used" 4 "Not used" 5 "Confirm address" 6 "Exit coding" 7 "Enter coding" ;
VAL_ 2467540809 D2M_IDX_DCDC_Index_09 0 "Initial Index" 1 "Index 1" 2 "Index 2" 3 "Index 3" 4 "Index 4" 5 "Index 5" 6 "Index 6" 7 "Index 7" 8 "Index 8" 9 "Index 9" 10 "Index 10" 11 "Index 11" 12 "Index 12" 13 "Index 13" 14 "Index 14" 15 "Index 15" 16 "Index 16" 17 "Index 17" 18 "Index 18" 19 "Index 19" 20 "Index 20" 21 "Index 21" 22 "Index 22" 23 "Index 23" 24 "Index 24" 25 "Index 25" 26 "Index 26" 27 "Index 27" 28 "Index 28" 29 "Index 29" 30 "Index 30" 31 "Index 31" 255 "Null" ;
VAL_ 2467540810 D2M_IDX_CMD_Type_10 0 "Invalid" 1 "Request address confirmation" 2 "Coding address" 3 "Not used" 4 "Not used" 5 "Confirm address" 6 "Exit coding" 7 "Enter coding" ;
VAL_ 2467540810 D2M_IDX_DCDC_Index_10 0 "Initial Index" 1 "Index 1" 2 "Index 2" 3 "Index 3" 4 "Index 4" 5 "Index 5" 6 "Index 6" 7 "Index 7" 8 "Index 8" 9 "Index 9" 10 "Index 10" 11 "Index 11" 12 "Index 12" 13 "Index 13" 14 "Index 14" 15 "Index 15" 16 "Index 16" 17 "Index 17" 18 "Index 18" 19 "Index 19" 20 "Index 20" 21 "Index 21" 22 "Index 22" 23 "Index 23" 24 "Index 24" 25 "Index 25" 26 "Index 26" 27 "Index 27" 28 "Index 28" 29 "Index 29" 30 "Index 30" 31 "Index 31" 255 "Null" ;
VAL_ 2467540811 D2M_IDX_CMD_Type_11 0 "Invalid" 1 "Request address confirmation" 2 "Coding address" 3 "Not used" 4 "Not used" 5 "Confirm address" 6 "Exit coding" 7 "Enter coding" ;
VAL_ 2467540811 D2M_IDX_DCDC_Index_11 0 "Initial Index" 1 "Index 1" 2 "Index 2" 3 "Index 3" 4 "Index 4" 5 "Index 5" 6 "Index 6" 7 "Index 7" 8 "Index 8" 9 "Index 9" 10 "Index 10" 11 "Index 11" 12 "Index 12" 13 "Index 13" 14 "Index 14" 15 "Index 15" 16 "Index 16" 17 "Index 17" 18 "Index 18" 19 "Index 19" 20 "Index 20" 21 "Index 21" 22 "Index 22" 23 "Index 23" 24 "Index 24" 25 "Index 25" 26 "Index 26" 27 "Index 27" 28 "Index 28" 29 "Index 29" 30 "Index 30" 31 "Index 31" 255 "Null" ;
VAL_ 2467540812 D2M_IDX_CMD_Type_12 0 "Invalid" 1 "Request address confirmation" 2 "Coding address" 3 "Not used" 4 "Not used" 5 "Confirm address" 6 "Exit coding" 7 "Enter coding" ;
VAL_ 2467540812 D2M_IDX_DCDC_Index_12 0 "Initial Index" 1 "Index 1" 2 "Index 2" 3 "Index 3" 4 "Index 4" 5 "Index 5" 6 "Index 6" 7 "Index 7" 8 "Index 8" 9 "Index 9" 10 "Index 10" 11 "Index 11" 12 "Index 12" 13 "Index 13" 14 "Index 14" 15 "Index 15" 16 "Index 16" 17 "Index 17" 18 "Index 18" 19 "Index 19" 20 "Index 20" 21 "Index 21" 22 "Index 22" 23 "Index 23" 24 "Index 24" 25 "Index 25" 26 "Index 26" 27 "Index 27" 28 "Index 28" 29 "Index 29" 30 "Index 30" 31 "Index 31" 255 "Null" ;
VAL_ 2467540813 D2M_IDX_CMD_Type_13 0 "Invalid" 1 "Request address confirmation" 2 "Coding address" 3 "Not used" 4 "Not used" 5 "Confirm address" 6 "Exit coding" 7 "Enter coding" ;
VAL_ 2467540813 D2M_IDX_DCDC_Index_13 0 "Initial Index" 1 "Index 1" 2 "Index 2" 3 "Index 3" 4 "Index 4" 5 "Index 5" 6 "Index 6" 7 "Index 7" 8 "Index 8" 9 "Index 9" 10 "Index 10" 11 "Index 11" 12 "Index 12" 13 "Index 13" 14 "Index 14" 15 "Index 15" 16 "Index 16" 17 "Index 17" 18 "Index 18" 19 "Index 19" 20 "Index 20" 21 "Index 21" 22 "Index 22" 23 "Index 23" 24 "Index 24" 25 "Index 25" 26 "Index 26" 27 "Index 27" 28 "Index 28" 29 "Index 29" 30 "Index 30" 31 "Index 31" 255 "Null" ;
VAL_ 2467540814 D2M_IDX_CMD_Type_14 0 "Invalid" 1 "Request address confirmation" 2 "Coding address" 3 "Not used" 4 "Not used" 5 "Confirm address" 6 "Exit coding" 7 "Enter coding" ;
VAL_ 2467540814 D2M_IDX_DCDC_Index_14 0 "Initial Index" 1 "Index 1" 2 "Index 2" 3 "Index 3" 4 "Index 4" 5 "Index 5" 6 "Index 6" 7 "Index 7" 8 "Index 8" 9 "Index 9" 10 "Index 10" 11 "Index 11" 12 "Index 12" 13 "Index 13" 14 "Index 14" 15 "Index 15" 16 "Index 16" 17 "Index 17" 18 "Index 18" 19 "Index 19" 20 "Index 20" 21 "Index 21" 22 "Index 22" 23 "Index 23" 24 "Index 24" 25 "Index 25" 26 "Index 26" 27 "Index 27" 28 "Index 28" 29 "Index 29" 30 "Index 30" 31 "Index 31" 255 "Null" ;
VAL_ 2467540815 D2M_IDX_CMD_Type_15 0 "Invalid" 1 "Request address confirmation" 2 "Coding address" 3 "Not used" 4 "Not used" 5 "Confirm address" 6 "Exit coding" 7 "Enter coding" ;
VAL_ 2467540815 D2M_IDX_DCDC_Index_15 0 "Initial Index" 1 "Index 1" 2 "Index 2" 3 "Index 3" 4 "Index 4" 5 "Index 5" 6 "Index 6" 7 "Index 7" 8 "Index 8" 9 "Index 9" 10 "Index 10" 11 "Index 11" 12 "Index 12" 13 "Index 13" 14 "Index 14" 15 "Index 15" 16 "Index 16" 17 "Index 17" 18 "Index 18" 19 "Index 19" 20 "Index 20" 21 "Index 21" 22 "Index 22" 23 "Index 23" 24 "Index 24" 25 "Index 25" 26 "Index 26" 27 "Index 27" 28 "Index 28" 29 "Index 29" 30 "Index 30" 31 "Index 31" 255 "Null" ;
VAL_ 2467540816 D2M_IDX_CMD_Type_16 0 "Invalid" 1 "Request address confirmation" 2 "Coding address" 3 "Not used" 4 "Not used" 5 "Confirm address" 6 "Exit coding" 7 "Enter coding" ;
VAL_ 2467540816 D2M_IDX_DCDC_Index_16 0 "Initial Index" 1 "Index 1" 2 "Index 2" 3 "Index 3" 4 "Index 4" 5 "Index 5" 6 "Index 6" 7 "Index 7" 8 "Index 8" 9 "Index 9" 10 "Index 10" 11 "Index 11" 12 "Index 12" 13 "Index 13" 14 "Index 14" 15 "Index 15" 16 "Index 16" 17 "Index 17" 18 "Index 18" 19 "Index 19" 20 "Index 20" 21 "Index 21" 22 "Index 22" 23 "Index 23" 24 "Index 24" 25 "Index 25" 26 "Index 26" 27 "Index 27" 28 "Index 28" 29 "Index 29" 30 "Index 30" 31 "Index 31" 255 "Null" ;
VAL_ 2467540817 D2M_IDX_CMD_Type_17 0 "Invalid" 1 "Request address confirmation" 2 "Coding address" 3 "Not used" 4 "Not used" 5 "Confirm address" 6 "Exit coding" 7 "Enter coding" ;
VAL_ 2467540817 D2M_IDX_DCDC_Index_17 0 "Initial Index" 1 "Index 1" 2 "Index 2" 3 "Index 3" 4 "Index 4" 5 "Index 5" 6 "Index 6" 7 "Index 7" 8 "Index 8" 9 "Index 9" 10 "Index 10" 11 "Index 11" 12 "Index 12" 13 "Index 13" 14 "Index 14" 15 "Index 15" 16 "Index 16" 17 "Index 17" 18 "Index 18" 19 "Index 19" 20 "Index 20" 21 "Index 21" 22 "Index 22" 23 "Index 23" 24 "Index 24" 25 "Index 25" 26 "Index 26" 27 "Index 27" 28 "Index 28" 29 "Index 29" 30 "Index 30" 31 "Index 31" 255 "Null" ;
VAL_ 2467540818 D2M_IDX_CMD_Type_18 0 "Invalid" 1 "Request address confirmation" 2 "Coding address" 3 "Not used" 4 "Not used" 5 "Confirm address" 6 "Exit coding" 7 "Enter coding" ;
VAL_ 2467540818 D2M_IDX_DCDC_Index_18 0 "Initial Index" 1 "Index 1" 2 "Index 2" 3 "Index 3" 4 "Index 4" 5 "Index 5" 6 "Index 6" 7 "Index 7" 8 "Index 8" 9 "Index 9" 10 "Index 10" 11 "Index 11" 12 "Index 12" 13 "Index 13" 14 "Index 14" 15 "Index 15" 16 "Index 16" 17 "Index 17" 18 "Index 18" 19 "Index 19" 20 "Index 20" 21 "Index 21" 22 "Index 22" 23 "Index 23" 24 "Index 24" 25 "Index 25" 26 "Index 26" 27 "Index 27" 28 "Index 28" 29 "Index 29" 30 "Index 30" 31 "Index 31" 255 "Null" ;
VAL_ 2467540819 D2M_IDX_CMD_Type_19 0 "Invalid" 1 "Request address confirmation" 2 "Coding address" 3 "Not used" 4 "Not used" 5 "Confirm address" 6 "Exit coding" 7 "Enter coding" ;
VAL_ 2467540819 D2M_IDX_DCDC_Index_19 0 "Initial Index" 1 "Index 1" 2 "Index 2" 3 "Index 3" 4 "Index 4" 5 "Index 5" 6 "Index 6" 7 "Index 7" 8 "Index 8" 9 "Index 9" 10 "Index 10" 11 "Index 11" 12 "Index 12" 13 "Index 13" 14 "Index 14" 15 "Index 15" 16 "Index 16" 17 "Index 17" 18 "Index 18" 19 "Index 19" 20 "Index 20" 21 "Index 21" 22 "Index 22" 23 "Index 23" 24 "Index 24" 25 "Index 25" 26 "Index 26" 27 "Index 27" 28 "Index 28" 29 "Index 29" 30 "Index 30" 31 "Index 31" 255 "Null" ;
VAL_ 2467540820 D2M_IDX_CMD_Type_20 0 "Invalid" 1 "Request address confirmation" 2 "Coding address" 3 "Not used" 4 "Not used" 5 "Confirm address" 6 "Exit coding" 7 "Enter coding" ;
VAL_ 2467540820 D2M_IDX_DCDC_Index_20 0 "Initial Index" 1 "Index 1" 2 "Index 2" 3 "Index 3" 4 "Index 4" 5 "Index 5" 6 "Index 6" 7 "Index 7" 8 "Index 8" 9 "Index 9" 10 "Index 10" 11 "Index 11" 12 "Index 12" 13 "Index 13" 14 "Index 14" 15 "Index 15" 16 "Index 16" 17 "Index 17" 18 "Index 18" 19 "Index 19" 20 "Index 20" 21 "Index 21" 22 "Index 22" 23 "Index 23" 24 "Index 24" 25 "Index 25" 26 "Index 26" 27 "Index 27" 28 "Index 28" 29 "Index 29" 30 "Index 30" 31 "Index 31" 255 "Null" ;
VAL_ 2467540821 D2M_IDX_CMD_Type_21 0 "Invalid" 1 "Request address confirmation" 2 "Coding address" 3 "Not used" 4 "Not used" 5 "Confirm address" 6 "Exit coding" 7 "Enter coding" ;
VAL_ 2467540821 D2M_IDX_DCDC_Index_21 0 "Initial Index" 1 "Index 1" 2 "Index 2" 3 "Index 3" 4 "Index 4" 5 "Index 5" 6 "Index 6" 7 "Index 7" 8 "Index 8" 9 "Index 9" 10 "Index 10" 11 "Index 11" 12 "Index 12" 13 "Index 13" 14 "Index 14" 15 "Index 15" 16 "Index 16" 17 "Index 17" 18 "Index 18" 19 "Index 19" 20 "Index 20" 21 "Index 21" 22 "Index 22" 23 "Index 23" 24 "Index 24" 25 "Index 25" 26 "Index 26" 27 "Index 27" 28 "Index 28" 29 "Index 29" 30 "Index 30" 31 "Index 31" 255 "Null" ;
VAL_ 2467540822 D2M_IDX_CMD_Type_22 0 "Invalid" 1 "Request address confirmation" 2 "Coding address" 3 "Not used" 4 "Not used" 5 "Confirm address" 6 "Exit coding" 7 "Enter coding" ;
VAL_ 2467540822 D2M_IDX_DCDC_Index_22 0 "Initial Index" 1 "Index 1" 2 "Index 2" 3 "Index 3" 4 "Index 4" 5 "Index 5" 6 "Index 6" 7 "Index 7" 8 "Index 8" 9 "Index 9" 10 "Index 10" 11 "Index 11" 12 "Index 12" 13 "Index 13" 14 "Index 14" 15 "Index 15" 16 "Index 16" 17 "Index 17" 18 "Index 18" 19 "Index 19" 20 "Index 20" 21 "Index 21" 22 "Index 22" 23 "Index 23" 24 "Index 24" 25 "Index 25" 26 "Index 26" 27 "Index 27" 28 "Index 28" 29 "Index 29" 30 "Index 30" 31 "Index 31" 255 "Null" ;
VAL_ 2467540823 D2M_IDX_CMD_Type_23 0 "Invalid" 1 "Request address confirmation" 2 "Coding address" 3 "Not used" 4 "Not used" 5 "Confirm address" 6 "Exit coding" 7 "Enter coding" ;
VAL_ 2467540823 D2M_IDX_DCDC_Index_23 0 "Initial Index" 1 "Index 1" 2 "Index 2" 3 "Index 3" 4 "Index 4" 5 "Index 5" 6 "Index 6" 7 "Index 7" 8 "Index 8" 9 "Index 9" 10 "Index 10" 11 "Index 11" 12 "Index 12" 13 "Index 13" 14 "Index 14" 15 "Index 15" 16 "Index 16" 17 "Index 17" 18 "Index 18" 19 "Index 19" 20 "Index 20" 21 "Index 21" 22 "Index 22" 23 "Index 23" 24 "Index 24" 25 "Index 25" 26 "Index 26" 27 "Index 27" 28 "Index 28" 29 "Index 29" 30 "Index 30" 31 "Index 31" 255 "Null" ;
VAL_ 2467540824 D2M_IDX_CMD_Type_24 0 "Invalid" 1 "Request address confirmation" 2 "Coding address" 3 "Not used" 4 "Not used" 5 "Confirm address" 6 "Exit coding" 7 "Enter coding" ;
VAL_ 2467540824 D2M_IDX_DCDC_Index_24 0 "Initial Index" 1 "Index 1" 2 "Index 2" 3 "Index 3" 4 "Index 4" 5 "Index 5" 6 "Index 6" 7 "Index 7" 8 "Index 8" 9 "Index 9" 10 "Index 10" 11 "Index 11" 12 "Index 12" 13 "Index 13" 14 "Index 14" 15 "Index 15" 16 "Index 16" 17 "Index 17" 18 "Index 18" 19 "Index 19" 20 "Index 20" 21 "Index 21" 22 "Index 22" 23 "Index 23" 24 "Index 24" 25 "Index 25" 26 "Index 26" 27 "Index 27" 28 "Index 28" 29 "Index 29" 30 "Index 30" 31 "Index 31" 255 "Null" ;
VAL_ 2467540825 D2M_IDX_CMD_Type_25 0 "Invalid" 1 "Request address confirmation" 2 "Coding address" 3 "Not used" 4 "Not used" 5 "Confirm address" 6 "Exit coding" 7 "Enter coding" ;
VAL_ 2467540825 D2M_IDX_DCDC_Index_25 0 "Initial Index" 1 "Index 1" 2 "Index 2" 3 "Index 3" 4 "Index 4" 5 "Index 5" 6 "Index 6" 7 "Index 7" 8 "Index 8" 9 "Index 9" 10 "Index 10" 11 "Index 11" 12 "Index 12" 13 "Index 13" 14 "Index 14" 15 "Index 15" 16 "Index 16" 17 "Index 17" 18 "Index 18" 19 "Index 19" 20 "Index 20" 21 "Index 21" 22 "Index 22" 23 "Index 23" 24 "Index 24" 25 "Index 25" 26 "Index 26" 27 "Index 27" 28 "Index 28" 29 "Index 29" 30 "Index 30" 31 "Index 31" 255 "Null" ;
VAL_ 2467540826 D2M_IDX_CMD_Type_26 0 "Invalid" 1 "Request address confirmation" 2 "Coding address" 3 "Not used" 4 "Not used" 5 "Confirm address" 6 "Exit coding" 7 "Enter coding" ;
VAL_ 2467540826 D2M_IDX_DCDC_Index_26 0 "Initial Index" 1 "Index 1" 2 "Index 2" 3 "Index 3" 4 "Index 4" 5 "Index 5" 6 "Index 6" 7 "Index 7" 8 "Index 8" 9 "Index 9" 10 "Index 10" 11 "Index 11" 12 "Index 12" 13 "Index 13" 14 "Index 14" 15 "Index 15" 16 "Index 16" 17 "Index 17" 18 "Index 18" 19 "Index 19" 20 "Index 20" 21 "Index 21" 22 "Index 22" 23 "Index 23" 24 "Index 24" 25 "Index 25" 26 "Index 26" 27 "Index 27" 28 "Index 28" 29 "Index 29" 30 "Index 30" 31 "Index 31" 255 "Null" ;
VAL_ 2467540827 D2M_IDX_CMD_Type_27 0 "Invalid" 1 "Request address confirmation" 2 "Coding address" 3 "Not used" 4 "Not used" 5 "Confirm address" 6 "Exit coding" 7 "Enter coding" ;
VAL_ 2467540827 D2M_IDX_DCDC_Index_27 0 "Initial Index" 1 "Index 1" 2 "Index 2" 3 "Index 3" 4 "Index 4" 5 "Index 5" 6 "Index 6" 7 "Index 7" 8 "Index 8" 9 "Index 9" 10 "Index 10" 11 "Index 11" 12 "Index 12" 13 "Index 13" 14 "Index 14" 15 "Index 15" 16 "Index 16" 17 "Index 17" 18 "Index 18" 19 "Index 19" 20 "Index 20" 21 "Index 21" 22 "Index 22" 23 "Index 23" 24 "Index 24" 25 "Index 25" 26 "Index 26" 27 "Index 27" 28 "Index 28" 29 "Index 29" 30 "Index 30" 31 "Index 31" 255 "Null" ;
VAL_ 2467540828 D2M_IDX_CMD_Type_28 0 "Invalid" 1 "Request address confirmation" 2 "Coding address" 3 "Not used" 4 "Not used" 5 "Confirm address" 6 "Exit coding" 7 "Enter coding" ;
VAL_ 2467540828 D2M_IDX_DCDC_Index_28 0 "Initial Index" 1 "Index 1" 2 "Index 2" 3 "Index 3" 4 "Index 4" 5 "Index 5" 6 "Index 6" 7 "Index 7" 8 "Index 8" 9 "Index 9" 10 "Index 10" 11 "Index 11" 12 "Index 12" 13 "Index 13" 14 "Index 14" 15 "Index 15" 16 "Index 16" 17 "Index 17" 18 "Index 18" 19 "Index 19" 20 "Index 20" 21 "Index 21" 22 "Index 22" 23 "Index 23" 24 "Index 24" 25 "Index 25" 26 "Index 26" 27 "Index 27" 28 "Index 28" 29 "Index 29" 30 "Index 30" 31 "Index 31" 255 "Null" ;
VAL_ 2467540829 D2M_IDX_CMD_Type_29 0 "Invalid" 1 "Request address confirmation" 2 "Coding address" 3 "Not used" 4 "Not used" 5 "Confirm address" 6 "Exit coding" 7 "Enter coding" ;
VAL_ 2467540829 D2M_IDX_DCDC_Index_29 0 "Initial Index" 1 "Index 1" 2 "Index 2" 3 "Index 3" 4 "Index 4" 5 "Index 5" 6 "Index 6" 7 "Index 7" 8 "Index 8" 9 "Index 9" 10 "Index 10" 11 "Index 11" 12 "Index 12" 13 "Index 13" 14 "Index 14" 15 "Index 15" 16 "Index 16" 17 "Index 17" 18 "Index 18" 19 "Index 19" 20 "Index 20" 21 "Index 21" 22 "Index 22" 23 "Index 23" 24 "Index 24" 25 "Index 25" 26 "Index 26" 27 "Index 27" 28 "Index 28" 29 "Index 29" 30 "Index 30" 31 "Index 31" 255 "Null" ;
VAL_ 2467540830 D2M_IDX_CMD_Type_30 0 "Invalid" 1 "Request address confirmation" 2 "Coding address" 3 "Not used" 4 "Not used" 5 "Confirm address" 6 "Exit coding" 7 "Enter coding" ;
VAL_ 2467540830 D2M_IDX_DCDC_Index_30 0 "Initial Index" 1 "Index 1" 2 "Index 2" 3 "Index 3" 4 "Index 4" 5 "Index 5" 6 "Index 6" 7 "Index 7" 8 "Index 8" 9 "Index 9" 10 "Index 10" 11 "Index 11" 12 "Index 12" 13 "Index 13" 14 "Index 14" 15 "Index 15" 16 "Index 16" 17 "Index 17" 18 "Index 18" 19 "Index 19" 20 "Index 20" 21 "Index 21" 22 "Index 22" 23 "Index 23" 24 "Index 24" 25 "Index 25" 26 "Index 26" 27 "Index 27" 28 "Index 28" 29 "Index 29" 30 "Index 30" 31 "Index 31" 255 "Null" ;
VAL_ 2467540831 D2M_IDX_CMD_Type_31 0 "Invalid" 1 "Request address confirmation" 2 "Coding address" 3 "Not used" 4 "Not used" 5 "Confirm address" 6 "Exit coding" 7 "Enter coding" ;
VAL_ 2467540831 D2M_IDX_DCDC_Index_31 0 "Initial Index" 1 "Index 1" 2 "Index 2" 3 "Index 3" 4 "Index 4" 5 "Index 5" 6 "Index 6" 7 "Index 7" 8 "Index 8" 9 "Index 9" 10 "Index 10" 11 "Index 11" 12 "Index 12" 13 "Index 13" 14 "Index 14" 15 "Index 15" 16 "Index 16" 17 "Index 17" 18 "Index 18" 19 "Index 19" 20 "Index 20" 21 "Index 21" 22 "Index 22" 23 "Index 23" 24 "Index 24" 25 "Index 25" 26 "Index 26" 27 "Index 27" 28 "Index 28" 29 "Index 29" 30 "Index 30" 31 "Index 31" 255 "Null" ;
VAL_ 2467540832 D2M_IDX_CMD_Type_32 0 "Invalid" 1 "Request address confirmation" 2 "Coding address" 3 "Not used" 4 "Not used" 5 "Confirm address" 6 "Exit coding" 7 "Enter coding" ;
VAL_ 2467540832 D2M_IDX_DCDC_Index_32 0 "Initial Index" 1 "Index 1" 2 "Index 2" 3 "Index 3" 4 "Index 4" 5 "Index 5" 6 "Index 6" 7 "Index 7" 8 "Index 8" 9 "Index 9" 10 "Index 10" 11 "Index 11" 12 "Index 12" 13 "Index 13" 14 "Index 14" 15 "Index 15" 16 "Index 16" 17 "Index 17" 18 "Index 18" 19 "Index 19" 20 "Index 20" 21 "Index 21" 22 "Index 22" 23 "Index 23" 24 "Index 24" 25 "Index 25" 26 "Index 26" 27 "Index 27" 28 "Index 28" 29 "Index 29" 30 "Index 30" 31 "Index 31" 255 "Null" ;
VAL_ 2467540833 D2M_IDX_CMD_Type_33 0 "Invalid" 1 "Request address confirmation" 2 "Coding address" 3 "Not used" 4 "Not used" 5 "Confirm address" 6 "Exit coding" 7 "Enter coding" ;
VAL_ 2467540833 D2M_IDX_DCDC_Index_33 0 "Initial Index" 1 "Index 1" 2 "Index 2" 3 "Index 3" 4 "Index 4" 5 "Index 5" 6 "Index 6" 7 "Index 7" 8 "Index 8" 9 "Index 9" 10 "Index 10" 11 "Index 11" 12 "Index 12" 13 "Index 13" 14 "Index 14" 15 "Index 15" 16 "Index 16" 17 "Index 17" 18 "Index 18" 19 "Index 19" 20 "Index 20" 21 "Index 21" 22 "Index 22" 23 "Index 23" 24 "Index 24" 25 "Index 25" 26 "Index 26" 27 "Index 27" 28 "Index 28" 29 "Index 29" 30 "Index 30" 31 "Index 31" 255 "Null" ;
VAL_ 2467540834 D2M_IDX_CMD_Type_34 0 "Invalid" 1 "Request address confirmation" 2 "Coding address" 3 "Not used" 4 "Not used" 5 "Confirm address" 6 "Exit coding" 7 "Enter coding" ;
VAL_ 2467540834 D2M_IDX_DCDC_Index_34 0 "Initial Index" 1 "Index 1" 2 "Index 2" 3 "Index 3" 4 "Index 4" 5 "Index 5" 6 "Index 6" 7 "Index 7" 8 "Index 8" 9 "Index 9" 10 "Index 10" 11 "Index 11" 12 "Index 12" 13 "Index 13" 14 "Index 14" 15 "Index 15" 16 "Index 16" 17 "Index 17" 18 "Index 18" 19 "Index 19" 20 "Index 20" 21 "Index 21" 22 "Index 22" 23 "Index 23" 24 "Index 24" 25 "Index 25" 26 "Index 26" 27 "Index 27" 28 "Index 28" 29 "Index 29" 30 "Index 30" 31 "Index 31" 255 "Null" ;
VAL_ 2467540835 D2M_IDX_CMD_Type_35 0 "Invalid" 1 "Request address confirmation" 2 "Coding address" 3 "Not used" 4 "Not used" 5 "Confirm address" 6 "Exit coding" 7 "Enter coding" ;
VAL_ 2467540835 D2M_IDX_DCDC_Index_35 0 "Initial Index" 1 "Index 1" 2 "Index 2" 3 "Index 3" 4 "Index 4" 5 "Index 5" 6 "Index 6" 7 "Index 7" 8 "Index 8" 9 "Index 9" 10 "Index 10" 11 "Index 11" 12 "Index 12" 13 "Index 13" 14 "Index 14" 15 "Index 15" 16 "Index 16" 17 "Index 17" 18 "Index 18" 19 "Index 19" 20 "Index 20" 21 "Index 21" 22 "Index 22" 23 "Index 23" 24 "Index 24" 25 "Index 25" 26 "Index 26" 27 "Index 27" 28 "Index 28" 29 "Index 29" 30 "Index 30" 31 "Index 31" 255 "Null" ;
VAL_ 2467540836 D2M_IDX_CMD_Type_36 0 "Invalid" 1 "Request address confirmation" 2 "Coding address" 3 "Not used" 4 "Not used" 5 "Confirm address" 6 "Exit coding" 7 "Enter coding" ;
VAL_ 2467540836 D2M_IDX_DCDC_Index_36 0 "Initial Index" 1 "Index 1" 2 "Index 2" 3 "Index 3" 4 "Index 4" 5 "Index 5" 6 "Index 6" 7 "Index 7" 8 "Index 8" 9 "Index 9" 10 "Index 10" 11 "Index 11" 12 "Index 12" 13 "Index 13" 14 "Index 14" 15 "Index 15" 16 "Index 16" 17 "Index 17" 18 "Index 18" 19 "Index 19" 20 "Index 20" 21 "Index 21" 22 "Index 22" 23 "Index 23" 24 "Index 24" 25 "Index 25" 26 "Index 26" 27 "Index 27" 28 "Index 28" 29 "Index 29" 30 "Index 30" 31 "Index 31" 255 "Null" ;
VAL_ 2467540837 D2M_IDX_CMD_Type_37 0 "Invalid" 1 "Request address confirmation" 2 "Coding address" 3 "Not used" 4 "Not used" 5 "Confirm address" 6 "Exit coding" 7 "Enter coding" ;
VAL_ 2467540837 D2M_IDX_DCDC_Index_37 0 "Initial Index" 1 "Index 1" 2 "Index 2" 3 "Index 3" 4 "Index 4" 5 "Index 5" 6 "Index 6" 7 "Index 7" 8 "Index 8" 9 "Index 9" 10 "Index 10" 11 "Index 11" 12 "Index 12" 13 "Index 13" 14 "Index 14" 15 "Index 15" 16 "Index 16" 17 "Index 17" 18 "Index 18" 19 "Index 19" 20 "Index 20" 21 "Index 21" 22 "Index 22" 23 "Index 23" 24 "Index 24" 25 "Index 25" 26 "Index 26" 27 "Index 27" 28 "Index 28" 29 "Index 29" 30 "Index 30" 31 "Index 31" 255 "Null" ;
VAL_ 2467540838 D2M_IDX_CMD_Type_38 0 "Invalid" 1 "Request address confirmation" 2 "Coding address" 3 "Not used" 4 "Not used" 5 "Confirm address" 6 "Exit coding" 7 "Enter coding" ;
VAL_ 2467540838 D2M_IDX_DCDC_Index_38 0 "Initial Index" 1 "Index 1" 2 "Index 2" 3 "Index 3" 4 "Index 4" 5 "Index 5" 6 "Index 6" 7 "Index 7" 8 "Index 8" 9 "Index 9" 10 "Index 10" 11 "Index 11" 12 "Index 12" 13 "Index 13" 14 "Index 14" 15 "Index 15" 16 "Index 16" 17 "Index 17" 18 "Index 18" 19 "Index 19" 20 "Index 20" 21 "Index 21" 22 "Index 22" 23 "Index 23" 24 "Index 24" 25 "Index 25" 26 "Index 26" 27 "Index 27" 28 "Index 28" 29 "Index 29" 30 "Index 30" 31 "Index 31" 255 "Null" ;
VAL_ 2467540839 D2M_IDX_CMD_Type_39 0 "Invalid" 1 "Request address confirmation" 2 "Coding address" 3 "Not used" 4 "Not used" 5 "Confirm address" 6 "Exit coding" 7 "Enter coding" ;
VAL_ 2467540839 D2M_IDX_DCDC_Index_39 0 "Initial Index" 1 "Index 1" 2 "Index 2" 3 "Index 3" 4 "Index 4" 5 "Index 5" 6 "Index 6" 7 "Index 7" 8 "Index 8" 9 "Index 9" 10 "Index 10" 11 "Index 11" 12 "Index 12" 13 "Index 13" 14 "Index 14" 15 "Index 15" 16 "Index 16" 17 "Index 17" 18 "Index 18" 19 "Index 19" 20 "Index 20" 21 "Index 21" 22 "Index 22" 23 "Index 23" 24 "Index 24" 25 "Index 25" 26 "Index 26" 27 "Index 27" 28 "Index 28" 29 "Index 29" 30 "Index 30" 31 "Index 31" 255 "Null" ;
VAL_ 2467540840 D2M_IDX_CMD_Type_40 0 "Invalid" 1 "Request address confirmation" 2 "Coding address" 3 "Not used" 4 "Not used" 5 "Confirm address" 6 "Exit coding" 7 "Enter coding" ;
VAL_ 2467540840 D2M_IDX_DCDC_Index_40 0 "Initial Index" 1 "Index 1" 2 "Index 2" 3 "Index 3" 4 "Index 4" 5 "Index 5" 6 "Index 6" 7 "Index 7" 8 "Index 8" 9 "Index 9" 10 "Index 10" 11 "Index 11" 12 "Index 12" 13 "Index 13" 14 "Index 14" 15 "Index 15" 16 "Index 16" 17 "Index 17" 18 "Index 18" 19 "Index 19" 20 "Index 20" 21 "Index 21" 22 "Index 22" 23 "Index 23" 24 "Index 24" 25 "Index 25" 26 "Index 26" 27 "Index 27" 28 "Index 28" 29 "Index 29" 30 "Index 30" 31 "Index 31" 255 "Null" ;
VAL_ 2467540841 D2M_IDX_CMD_Type_41 0 "Invalid" 1 "Request address confirmation" 2 "Coding address" 3 "Not used" 4 "Not used" 5 "Confirm address" 6 "Exit coding" 7 "Enter coding" ;
VAL_ 2467540841 D2M_IDX_DCDC_Index_41 0 "Initial Index" 1 "Index 1" 2 "Index 2" 3 "Index 3" 4 "Index 4" 5 "Index 5" 6 "Index 6" 7 "Index 7" 8 "Index 8" 9 "Index 9" 10 "Index 10" 11 "Index 11" 12 "Index 12" 13 "Index 13" 14 "Index 14" 15 "Index 15" 16 "Index 16" 17 "Index 17" 18 "Index 18" 19 "Index 19" 20 "Index 20" 21 "Index 21" 22 "Index 22" 23 "Index 23" 24 "Index 24" 25 "Index 25" 26 "Index 26" 27 "Index 27" 28 "Index 28" 29 "Index 29" 30 "Index 30" 31 "Index 31" 255 "Null" ;
VAL_ 2467540842 D2M_IDX_CMD_Type_42 0 "Invalid" 1 "Request address confirmation" 2 "Coding address" 3 "Not used" 4 "Not used" 5 "Confirm address" 6 "Exit coding" 7 "Enter coding" ;
VAL_ 2467540842 D2M_IDX_DCDC_Index_42 0 "Initial Index" 1 "Index 1" 2 "Index 2" 3 "Index 3" 4 "Index 4" 5 "Index 5" 6 "Index 6" 7 "Index 7" 8 "Index 8" 9 "Index 9" 10 "Index 10" 11 "Index 11" 12 "Index 12" 13 "Index 13" 14 "Index 14" 15 "Index 15" 16 "Index 16" 17 "Index 17" 18 "Index 18" 19 "Index 19" 20 "Index 20" 21 "Index 21" 22 "Index 22" 23 "Index 23" 24 "Index 24" 25 "Index 25" 26 "Index 26" 27 "Index 27" 28 "Index 28" 29 "Index 29" 30 "Index 30" 31 "Index 31" 255 "Null" ;
VAL_ 2467540843 D2M_IDX_CMD_Type_43 0 "Invalid" 1 "Request address confirmation" 2 "Coding address" 3 "Not used" 4 "Not used" 5 "Confirm address" 6 "Exit coding" 7 "Enter coding" ;
VAL_ 2467540843 D2M_IDX_DCDC_Index_43 0 "Initial Index" 1 "Index 1" 2 "Index 2" 3 "Index 3" 4 "Index 4" 5 "Index 5" 6 "Index 6" 7 "Index 7" 8 "Index 8" 9 "Index 9" 10 "Index 10" 11 "Index 11" 12 "Index 12" 13 "Index 13" 14 "Index 14" 15 "Index 15" 16 "Index 16" 17 "Index 17" 18 "Index 18" 19 "Index 19" 20 "Index 20" 21 "Index 21" 22 "Index 22" 23 "Index 23" 24 "Index 24" 25 "Index 25" 26 "Index 26" 27 "Index 27" 28 "Index 28" 29 "Index 29" 30 "Index 30" 31 "Index 31" 255 "Null" ;
VAL_ 2467540844 D2M_IDX_CMD_Type_44 0 "Invalid" 1 "Request address confirmation" 2 "Coding address" 3 "Not used" 4 "Not used" 5 "Confirm address" 6 "Exit coding" 7 "Enter coding" ;
VAL_ 2467540844 D2M_IDX_DCDC_Index_44 0 "Initial Index" 1 "Index 1" 2 "Index 2" 3 "Index 3" 4 "Index 4" 5 "Index 5" 6 "Index 6" 7 "Index 7" 8 "Index 8" 9 "Index 9" 10 "Index 10" 11 "Index 11" 12 "Index 12" 13 "Index 13" 14 "Index 14" 15 "Index 15" 16 "Index 16" 17 "Index 17" 18 "Index 18" 19 "Index 19" 20 "Index 20" 21 "Index 21" 22 "Index 22" 23 "Index 23" 24 "Index 24" 25 "Index 25" 26 "Index 26" 27 "Index 27" 28 "Index 28" 29 "Index 29" 30 "Index 30" 31 "Index 31" 255 "Null" ;
VAL_ 2467540845 D2M_IDX_CMD_Type_45 0 "Invalid" 1 "Request address confirmation" 2 "Coding address" 3 "Not used" 4 "Not used" 5 "Confirm address" 6 "Exit coding" 7 "Enter coding" ;
VAL_ 2467540845 D2M_IDX_DCDC_Index_45 0 "Initial Index" 1 "Index 1" 2 "Index 2" 3 "Index 3" 4 "Index 4" 5 "Index 5" 6 "Index 6" 7 "Index 7" 8 "Index 8" 9 "Index 9" 10 "Index 10" 11 "Index 11" 12 "Index 12" 13 "Index 13" 14 "Index 14" 15 "Index 15" 16 "Index 16" 17 "Index 17" 18 "Index 18" 19 "Index 19" 20 "Index 20" 21 "Index 21" 22 "Index 22" 23 "Index 23" 24 "Index 24" 25 "Index 25" 26 "Index 26" 27 "Index 27" 28 "Index 28" 29 "Index 29" 30 "Index 30" 31 "Index 31" 255 "Null" ;
VAL_ 2467540846 D2M_IDX_CMD_Type_46 0 "Invalid" 1 "Request address confirmation" 2 "Coding address" 3 "Not used" 4 "Not used" 5 "Confirm address" 6 "Exit coding" 7 "Enter coding" ;
VAL_ 2467540846 D2M_IDX_DCDC_Index_46 0 "Initial Index" 1 "Index 1" 2 "Index 2" 3 "Index 3" 4 "Index 4" 5 "Index 5" 6 "Index 6" 7 "Index 7" 8 "Index 8" 9 "Index 9" 10 "Index 10" 11 "Index 11" 12 "Index 12" 13 "Index 13" 14 "Index 14" 15 "Index 15" 16 "Index 16" 17 "Index 17" 18 "Index 18" 19 "Index 19" 20 "Index 20" 21 "Index 21" 22 "Index 22" 23 "Index 23" 24 "Index 24" 25 "Index 25" 26 "Index 26" 27 "Index 27" 28 "Index 28" 29 "Index 29" 30 "Index 30" 31 "Index 31" 255 "Null" ;
VAL_ 2467540847 D2M_IDX_CMD_Type_47 0 "Invalid" 1 "Request address confirmation" 2 "Coding address" 3 "Not used" 4 "Not used" 5 "Confirm address" 6 "Exit coding" 7 "Enter coding" ;
VAL_ 2467540847 D2M_IDX_DCDC_Index_47 0 "Initial Index" 1 "Index 1" 2 "Index 2" 3 "Index 3" 4 "Index 4" 5 "Index 5" 6 "Index 6" 7 "Index 7" 8 "Index 8" 9 "Index 9" 10 "Index 10" 11 "Index 11" 12 "Index 12" 13 "Index 13" 14 "Index 14" 15 "Index 15" 16 "Index 16" 17 "Index 17" 18 "Index 18" 19 "Index 19" 20 "Index 20" 21 "Index 21" 22 "Index 22" 23 "Index 23" 24 "Index 24" 25 "Index 25" 26 "Index 26" 27 "Index 27" 28 "Index 28" 29 "Index 29" 30 "Index 30" 31 "Index 31" 255 "Null" ;
VAL_ 2467540848 D2M_IDX_CMD_Type_48 0 "Invalid" 1 "Request address confirmation" 2 "Coding address" 3 "Not used" 4 "Not used" 5 "Confirm address" 6 "Exit coding" 7 "Enter coding" ;
VAL_ 2467540848 D2M_IDX_DCDC_Index_48 0 "Initial Index" 1 "Index 1" 2 "Index 2" 3 "Index 3" 4 "Index 4" 5 "Index 5" 6 "Index 6" 7 "Index 7" 8 "Index 8" 9 "Index 9" 10 "Index 10" 11 "Index 11" 12 "Index 12" 13 "Index 13" 14 "Index 14" 15 "Index 15" 16 "Index 16" 17 "Index 17" 18 "Index 18" 19 "Index 19" 20 "Index 20" 21 "Index 21" 22 "Index 22" 23 "Index 23" 24 "Index 24" 25 "Index 25" 26 "Index 26" 27 "Index 27" 28 "Index 28" 29 "Index 29" 30 "Index 30" 31 "Index 31" 255 "Null" ;
VAL_ 2467540849 D2M_IDX_CMD_Type_49 0 "Invalid" 1 "Request address confirmation" 2 "Coding address" 3 "Not used" 4 "Not used" 5 "Confirm address" 6 "Exit coding" 7 "Enter coding" ;
VAL_ 2467540849 D2M_IDX_DCDC_Index_49 0 "Initial Index" 1 "Index 1" 2 "Index 2" 3 "Index 3" 4 "Index 4" 5 "Index 5" 6 "Index 6" 7 "Index 7" 8 "Index 8" 9 "Index 9" 10 "Index 10" 11 "Index 11" 12 "Index 12" 13 "Index 13" 14 "Index 14" 15 "Index 15" 16 "Index 16" 17 "Index 17" 18 "Index 18" 19 "Index 19" 20 "Index 20" 21 "Index 21" 22 "Index 22" 23 "Index 23" 24 "Index 24" 25 "Index 25" 26 "Index 26" 27 "Index 27" 28 "Index 28" 29 "Index 29" 30 "Index 30" 31 "Index 31" 255 "Null" ;
VAL_ 2467540850 D2M_IDX_CMD_Type_50 0 "Invalid" 1 "Request address confirmation" 2 "Coding address" 3 "Not used" 4 "Not used" 5 "Confirm address" 6 "Exit coding" 7 "Enter coding" ;
VAL_ 2467540850 D2M_IDX_DCDC_Index_50 0 "Initial Index" 1 "Index 1" 2 "Index 2" 3 "Index 3" 4 "Index 4" 5 "Index 5" 6 "Index 6" 7 "Index 7" 8 "Index 8" 9 "Index 9" 10 "Index 10" 11 "Index 11" 12 "Index 12" 13 "Index 13" 14 "Index 14" 15 "Index 15" 16 "Index 16" 17 "Index 17" 18 "Index 18" 19 "Index 19" 20 "Index 20" 21 "Index 21" 22 "Index 22" 23 "Index 23" 24 "Index 24" 25 "Index 25" 26 "Index 26" 27 "Index 27" 28 "Index 28" 29 "Index 29" 30 "Index 30" 31 "Index 31" 255 "Null" ;
VAL_ 2467540851 D2M_IDX_CMD_Type_51 0 "Invalid" 1 "Request address confirmation" 2 "Coding address" 3 "Not used" 4 "Not used" 5 "Confirm address" 6 "Exit coding" 7 "Enter coding" ;
VAL_ 2467540851 D2M_IDX_DCDC_Index_51 0 "Initial Index" 1 "Index 1" 2 "Index 2" 3 "Index 3" 4 "Index 4" 5 "Index 5" 6 "Index 6" 7 "Index 7" 8 "Index 8" 9 "Index 9" 10 "Index 10" 11 "Index 11" 12 "Index 12" 13 "Index 13" 14 "Index 14" 15 "Index 15" 16 "Index 16" 17 "Index 17" 18 "Index 18" 19 "Index 19" 20 "Index 20" 21 "Index 21" 22 "Index 22" 23 "Index 23" 24 "Index 24" 25 "Index 25" 26 "Index 26" 27 "Index 27" 28 "Index 28" 29 "Index 29" 30 "Index 30" 31 "Index 31" 255 "Null" ;
VAL_ 2467540852 D2M_IDX_CMD_Type_52 0 "Invalid" 1 "Request address confirmation" 2 "Coding address" 3 "Not used" 4 "Not used" 5 "Confirm address" 6 "Exit coding" 7 "Enter coding" ;
VAL_ 2467540852 D2M_IDX_DCDC_Index_52 0 "Initial Index" 1 "Index 1" 2 "Index 2" 3 "Index 3" 4 "Index 4" 5 "Index 5" 6 "Index 6" 7 "Index 7" 8 "Index 8" 9 "Index 9" 10 "Index 10" 11 "Index 11" 12 "Index 12" 13 "Index 13" 14 "Index 14" 15 "Index 15" 16 "Index 16" 17 "Index 17" 18 "Index 18" 19 "Index 19" 20 "Index 20" 21 "Index 21" 22 "Index 22" 23 "Index 23" 24 "Index 24" 25 "Index 25" 26 "Index 26" 27 "Index 27" 28 "Index 28" 29 "Index 29" 30 "Index 30" 31 "Index 31" 255 "Null" ;
VAL_ 2467540853 D2M_IDX_CMD_Type_53 0 "Invalid" 1 "Request address confirmation" 2 "Coding address" 3 "Not used" 4 "Not used" 5 "Confirm address" 6 "Exit coding" 7 "Enter coding" ;
VAL_ 2467540853 D2M_IDX_DCDC_Index_53 0 "Initial Index" 1 "Index 1" 2 "Index 2" 3 "Index 3" 4 "Index 4" 5 "Index 5" 6 "Index 6" 7 "Index 7" 8 "Index 8" 9 "Index 9" 10 "Index 10" 11 "Index 11" 12 "Index 12" 13 "Index 13" 14 "Index 14" 15 "Index 15" 16 "Index 16" 17 "Index 17" 18 "Index 18" 19 "Index 19" 20 "Index 20" 21 "Index 21" 22 "Index 22" 23 "Index 23" 24 "Index 24" 25 "Index 25" 26 "Index 26" 27 "Index 27" 28 "Index 28" 29 "Index 29" 30 "Index 30" 31 "Index 31" 255 "Null" ;
VAL_ 2467540854 D2M_IDX_CMD_Type_54 0 "Invalid" 1 "Request address confirmation" 2 "Coding address" 3 "Not used" 4 "Not used" 5 "Confirm address" 6 "Exit coding" 7 "Enter coding" ;
VAL_ 2467540854 D2M_IDX_DCDC_Index_54 0 "Initial Index" 1 "Index 1" 2 "Index 2" 3 "Index 3" 4 "Index 4" 5 "Index 5" 6 "Index 6" 7 "Index 7" 8 "Index 8" 9 "Index 9" 10 "Index 10" 11 "Index 11" 12 "Index 12" 13 "Index 13" 14 "Index 14" 15 "Index 15" 16 "Index 16" 17 "Index 17" 18 "Index 18" 19 "Index 19" 20 "Index 20" 21 "Index 21" 22 "Index 22" 23 "Index 23" 24 "Index 24" 25 "Index 25" 26 "Index 26" 27 "Index 27" 28 "Index 28" 29 "Index 29" 30 "Index 30" 31 "Index 31" 255 "Null" ;
VAL_ 2467540855 D2M_IDX_CMD_Type_55 0 "Invalid" 1 "Request address confirmation" 2 "Coding address" 3 "Not used" 4 "Not used" 5 "Confirm address" 6 "Exit coding" 7 "Enter coding" ;
VAL_ 2467540855 D2M_IDX_DCDC_Index_55 0 "Initial Index" 1 "Index 1" 2 "Index 2" 3 "Index 3" 4 "Index 4" 5 "Index 5" 6 "Index 6" 7 "Index 7" 8 "Index 8" 9 "Index 9" 10 "Index 10" 11 "Index 11" 12 "Index 12" 13 "Index 13" 14 "Index 14" 15 "Index 15" 16 "Index 16" 17 "Index 17" 18 "Index 18" 19 "Index 19" 20 "Index 20" 21 "Index 21" 22 "Index 22" 23 "Index 23" 24 "Index 24" 25 "Index 25" 26 "Index 26" 27 "Index 27" 28 "Index 28" 29 "Index 29" 30 "Index 30" 31 "Index 31" 255 "Null" ;
VAL_ 2467540856 D2M_IDX_CMD_Type_56 0 "Invalid" 1 "Request address confirmation" 2 "Coding address" 3 "Not used" 4 "Not used" 5 "Confirm address" 6 "Exit coding" 7 "Enter coding" ;
VAL_ 2467540856 D2M_IDX_DCDC_Index_56 0 "Initial Index" 1 "Index 1" 2 "Index 2" 3 "Index 3" 4 "Index 4" 5 "Index 5" 6 "Index 6" 7 "Index 7" 8 "Index 8" 9 "Index 9" 10 "Index 10" 11 "Index 11" 12 "Index 12" 13 "Index 13" 14 "Index 14" 15 "Index 15" 16 "Index 16" 17 "Index 17" 18 "Index 18" 19 "Index 19" 20 "Index 20" 21 "Index 21" 22 "Index 22" 23 "Index 23" 24 "Index 24" 25 "Index 25" 26 "Index 26" 27 "Index 27" 28 "Index 28" 29 "Index 29" 30 "Index 30" 31 "Index 31" 255 "Null" ;
VAL_ 2467540857 D2M_IDX_CMD_Type_57 0 "Invalid" 1 "Request address confirmation" 2 "Coding address" 3 "Not used" 4 "Not used" 5 "Confirm address" 6 "Exit coding" 7 "Enter coding" ;
VAL_ 2467540857 D2M_IDX_DCDC_Index_57 0 "Initial Index" 1 "Index 1" 2 "Index 2" 3 "Index 3" 4 "Index 4" 5 "Index 5" 6 "Index 6" 7 "Index 7" 8 "Index 8" 9 "Index 9" 10 "Index 10" 11 "Index 11" 12 "Index 12" 13 "Index 13" 14 "Index 14" 15 "Index 15" 16 "Index 16" 17 "Index 17" 18 "Index 18" 19 "Index 19" 20 "Index 20" 21 "Index 21" 22 "Index 22" 23 "Index 23" 24 "Index 24" 25 "Index 25" 26 "Index 26" 27 "Index 27" 28 "Index 28" 29 "Index 29" 30 "Index 30" 31 "Index 31" 255 "Null" ;
VAL_ 2467540858 D2M_IDX_CMD_Type_58 0 "Invalid" 1 "Request address confirmation" 2 "Coding address" 3 "Not used" 4 "Not used" 5 "Confirm address" 6 "Exit coding" 7 "Enter coding" ;
VAL_ 2467540858 D2M_IDX_DCDC_Index_58 0 "Initial Index" 1 "Index 1" 2 "Index 2" 3 "Index 3" 4 "Index 4" 5 "Index 5" 6 "Index 6" 7 "Index 7" 8 "Index 8" 9 "Index 9" 10 "Index 10" 11 "Index 11" 12 "Index 12" 13 "Index 13" 14 "Index 14" 15 "Index 15" 16 "Index 16" 17 "Index 17" 18 "Index 18" 19 "Index 19" 20 "Index 20" 21 "Index 21" 22 "Index 22" 23 "Index 23" 24 "Index 24" 25 "Index 25" 26 "Index 26" 27 "Index 27" 28 "Index 28" 29 "Index 29" 30 "Index 30" 31 "Index 31" 255 "Null" ;
VAL_ 2467540859 D2M_IDX_CMD_Type_59 0 "Invalid" 1 "Request address confirmation" 2 "Coding address" 3 "Not used" 4 "Not used" 5 "Confirm address" 6 "Exit coding" 7 "Enter coding" ;
VAL_ 2467540859 D2M_IDX_DCDC_Index_59 0 "Initial Index" 1 "Index 1" 2 "Index 2" 3 "Index 3" 4 "Index 4" 5 "Index 5" 6 "Index 6" 7 "Index 7" 8 "Index 8" 9 "Index 9" 10 "Index 10" 11 "Index 11" 12 "Index 12" 13 "Index 13" 14 "Index 14" 15 "Index 15" 16 "Index 16" 17 "Index 17" 18 "Index 18" 19 "Index 19" 20 "Index 20" 21 "Index 21" 22 "Index 22" 23 "Index 23" 24 "Index 24" 25 "Index 25" 26 "Index 26" 27 "Index 27" 28 "Index 28" 29 "Index 29" 30 "Index 30" 31 "Index 31" 255 "Null" ;
VAL_ 2467540860 D2M_IDX_CMD_Type_60 0 "Invalid" 1 "Request address confirmation" 2 "Coding address" 3 "Not used" 4 "Not used" 5 "Confirm address" 6 "Exit coding" 7 "Enter coding" ;
VAL_ 2467540860 D2M_IDX_DCDC_Index_60 0 "Initial Index" 1 "Index 1" 2 "Index 2" 3 "Index 3" 4 "Index 4" 5 "Index 5" 6 "Index 6" 7 "Index 7" 8 "Index 8" 9 "Index 9" 10 "Index 10" 11 "Index 11" 12 "Index 12" 13 "Index 13" 14 "Index 14" 15 "Index 15" 16 "Index 16" 17 "Index 17" 18 "Index 18" 19 "Index 19" 20 "Index 20" 21 "Index 21" 22 "Index 22" 23 "Index 23" 24 "Index 24" 25 "Index 25" 26 "Index 26" 27 "Index 27" 28 "Index 28" 29 "Index 29" 30 "Index 30" 31 "Index 31" 255 "Null" ;
VAL_ 2467540861 D2M_IDX_CMD_Type_61 0 "Invalid" 1 "Request address confirmation" 2 "Coding address" 3 "Not used" 4 "Not used" 5 "Confirm address" 6 "Exit coding" 7 "Enter coding" ;
VAL_ 2467540861 D2M_IDX_DCDC_Index_61 0 "Initial Index" 1 "Index 1" 2 "Index 2" 3 "Index 3" 4 "Index 4" 5 "Index 5" 6 "Index 6" 7 "Index 7" 8 "Index 8" 9 "Index 9" 10 "Index 10" 11 "Index 11" 12 "Index 12" 13 "Index 13" 14 "Index 14" 15 "Index 15" 16 "Index 16" 17 "Index 17" 18 "Index 18" 19 "Index 19" 20 "Index 20" 21 "Index 21" 22 "Index 22" 23 "Index 23" 24 "Index 24" 25 "Index 25" 26 "Index 26" 27 "Index 27" 28 "Index 28" 29 "Index 29" 30 "Index 30" 31 "Index 31" 255 "Null" ;
VAL_ 2467540862 D2M_IDX_CMD_Type_62 0 "Invalid" 1 "Request address confirmation" 2 "Coding address" 3 "Not used" 4 "Not used" 5 "Confirm address" 6 "Exit coding" 7 "Enter coding" ;
VAL_ 2467540862 D2M_IDX_DCDC_Index_62 0 "Initial Index" 1 "Index 1" 2 "Index 2" 3 "Index 3" 4 "Index 4" 5 "Index 5" 6 "Index 6" 7 "Index 7" 8 "Index 8" 9 "Index 9" 10 "Index 10" 11 "Index 11" 12 "Index 12" 13 "Index 13" 14 "Index 14" 15 "Index 15" 16 "Index 16" 17 "Index 17" 18 "Index 18" 19 "Index 19" 20 "Index 20" 21 "Index 21" 22 "Index 22" 23 "Index 23" 24 "Index 24" 25 "Index 25" 26 "Index 26" 27 "Index 27" 28 "Index 28" 29 "Index 29" 30 "Index 30" 31 "Index 31" 255 "Null" ;
VAL_ 2467540863 D2M_IDX_CMD_Type_63 0 "Invalid" 1 "Request address confirmation" 2 "Coding address" 3 "Not used" 4 "Not used" 5 "Confirm address" 6 "Exit coding" 7 "Enter coding" ;
VAL_ 2467540863 D2M_IDX_DCDC_Index_63 0 "Initial Index" 1 "Index 1" 2 "Index 2" 3 "Index 3" 4 "Index 4" 5 "Index 5" 6 "Index 6" 7 "Index 7" 8 "Index 8" 9 "Index 9" 10 "Index 10" 11 "Index 11" 12 "Index 12" 13 "Index 13" 14 "Index 14" 15 "Index 15" 16 "Index 16" 17 "Index 17" 18 "Index 18" 19 "Index 19" 20 "Index 20" 21 "Index 21" 22 "Index 22" 23 "Index 23" 24 "Index 24" 25 "Index 25" 26 "Index 26" 27 "Index 27" 28 "Index 28" 29 "Index 29" 30 "Index 30" 31 "Index 31" 255 "Null" ;
VAL_ 2333343553 S2A_TRDM_ThrmlRnwyFltCseMsk_01 1 "bit0:欠压和过温" 2 "bit1:欠压和温升速率过大" 4 "bit2:欠压和温差过大" 8 "bit3:温升速率过大和过温" 16 "bit4:温升速率过大和温差过大" 32 "bit5:采样线掉线和过温" 64 "bit6:采样线掉线和温升速率过大" 128 "bit7采样线掉线和温差过大" ;
VAL_ 2333343553 S2A_TRDM_ThrmlRnwyFltCSC_01 1 "CSC1#" 2 "CSC2#" 3 "CSC3#" 4 "CSC4#" 5 "CSC5#" 6 "CSC6#" 7 "CSC7#" 8 "CSC8#" ;
VAL_ 2333343554 S2A_TRDM_ThrmlRnwyFltCseMsk_02 1 "bit0:欠压和过温" 2 "bit1:欠压和温升速率过大" 4 "bit2:欠压和温差过大" 8 "bit3:温升速率过大和过温" 16 "bit4:温升速率过大和温差过大" 32 "bit5:采样线掉线和过温" 64 "bit6:采样线掉线和温升速率过大" 128 "bit7采样线掉线和温差过大" ;
VAL_ 2333343554 S2A_TRDM_ThrmlRnwyFltCSC_02 1 "CSC1#" 2 "CSC2#" 3 "CSC3#" 4 "CSC4#" 5 "CSC5#" 6 "CSC6#" 7 "CSC7#" 8 "CSC8#" ;
VAL_ 2333343555 S2A_TRDM_ThrmlRnwyFltCseMsk_03 1 "bit0:欠压和过温" 2 "bit1:欠压和温升速率过大" 4 "bit2:欠压和温差过大" 8 "bit3:温升速率过大和过温" 16 "bit4:温升速率过大和温差过大" 32 "bit5:采样线掉线和过温" 64 "bit6:采样线掉线和温升速率过大" 128 "bit7采样线掉线和温差过大" ;
VAL_ 2333343555 S2A_TRDM_ThrmlRnwyFltCSC_03 1 "CSC1#" 2 "CSC2#" 3 "CSC3#" 4 "CSC4#" 5 "CSC5#" 6 "CSC6#" 7 "CSC7#" 8 "CSC8#" ;
VAL_ 2333343556 S2A_TRDM_ThrmlRnwyFltCseMsk_04 1 "bit0:欠压和过温" 2 "bit1:欠压和温升速率过大" 4 "bit2:欠压和温差过大" 8 "bit3:温升速率过大和过温" 16 "bit4:温升速率过大和温差过大" 32 "bit5:采样线掉线和过温" 64 "bit6:采样线掉线和温升速率过大" 128 "bit7采样线掉线和温差过大" ;
VAL_ 2333343556 S2A_TRDM_ThrmlRnwyFltCSC_04 1 "CSC1#" 2 "CSC2#" 3 "CSC3#" 4 "CSC4#" 5 "CSC5#" 6 "CSC6#" 7 "CSC7#" 8 "CSC8#" ;
VAL_ 2333343557 S2A_TRDM_ThrmlRnwyFltCseMsk_05 1 "bit0:欠压和过温" 2 "bit1:欠压和温升速率过大" 4 "bit2:欠压和温差过大" 8 "bit3:温升速率过大和过温" 16 "bit4:温升速率过大和温差过大" 32 "bit5:采样线掉线和过温" 64 "bit6:采样线掉线和温升速率过大" 128 "bit7采样线掉线和温差过大" ;
VAL_ 2333343557 S2A_TRDM_ThrmlRnwyFltCSC_05 1 "CSC1#" 2 "CSC2#" 3 "CSC3#" 4 "CSC4#" 5 "CSC5#" 6 "CSC6#" 7 "CSC7#" 8 "CSC8#" ;
VAL_ 2333343558 S2A_TRDM_ThrmlRnwyFltCseMsk_06 1 "bit0:欠压和过温" 2 "bit1:欠压和温升速率过大" 4 "bit2:欠压和温差过大" 8 "bit3:温升速率过大和过温" 16 "bit4:温升速率过大和温差过大" 32 "bit5:采样线掉线和过温" 64 "bit6:采样线掉线和温升速率过大" 128 "bit7采样线掉线和温差过大" ;
VAL_ 2333343558 S2A_TRDM_ThrmlRnwyFltCSC_06 1 "CSC1#" 2 "CSC2#" 3 "CSC3#" 4 "CSC4#" 5 "CSC5#" 6 "CSC6#" 7 "CSC7#" 8 "CSC8#" ;
VAL_ 2333343559 S2A_TRDM_ThrmlRnwyFltCseMsk_07 1 "bit0:欠压和过温" 2 "bit1:欠压和温升速率过大" 4 "bit2:欠压和温差过大" 8 "bit3:温升速率过大和过温" 16 "bit4:温升速率过大和温差过大" 32 "bit5:采样线掉线和过温" 64 "bit6:采样线掉线和温升速率过大" 128 "bit7采样线掉线和温差过大" ;
VAL_ 2333343559 S2A_TRDM_ThrmlRnwyFltCSC_07 1 "CSC1#" 2 "CSC2#" 3 "CSC3#" 4 "CSC4#" 5 "CSC5#" 6 "CSC6#" 7 "CSC7#" 8 "CSC8#" ;
VAL_ 2333343560 S2A_TRDM_ThrmlRnwyFltCseMsk_08 1 "bit0:欠压和过温" 2 "bit1:欠压和温升速率过大" 4 "bit2:欠压和温差过大" 8 "bit3:温升速率过大和过温" 16 "bit4:温升速率过大和温差过大" 32 "bit5:采样线掉线和过温" 64 "bit6:采样线掉线和温升速率过大" 128 "bit7采样线掉线和温差过大" ;
VAL_ 2333343560 S2A_TRDM_ThrmlRnwyFltCSC_08 1 "CSC1#" 2 "CSC2#" 3 "CSC3#" 4 "CSC4#" 5 "CSC5#" 6 "CSC6#" 7 "CSC7#" 8 "CSC8#" ;
VAL_ 2333343561 S2A_TRDM_ThrmlRnwyFltCseMsk_09 1 "bit0:欠压和过温" 2 "bit1:欠压和温升速率过大" 4 "bit2:欠压和温差过大" 8 "bit3:温升速率过大和过温" 16 "bit4:温升速率过大和温差过大" 32 "bit5:采样线掉线和过温" 64 "bit6:采样线掉线和温升速率过大" 128 "bit7采样线掉线和温差过大" ;
VAL_ 2333343561 S2A_TRDM_ThrmlRnwyFltCSC_09 1 "CSC1#" 2 "CSC2#" 3 "CSC3#" 4 "CSC4#" 5 "CSC5#" 6 "CSC6#" 7 "CSC7#" 8 "CSC8#" ;
VAL_ 2333343562 S2A_TRDM_ThrmlRnwyFltCseMsk_10 1 "bit0:欠压和过温" 2 "bit1:欠压和温升速率过大" 4 "bit2:欠压和温差过大" 8 "bit3:温升速率过大和过温" 16 "bit4:温升速率过大和温差过大" 32 "bit5:采样线掉线和过温" 64 "bit6:采样线掉线和温升速率过大" 128 "bit7采样线掉线和温差过大" ;
VAL_ 2333343562 S2A_TRDM_ThrmlRnwyFltCSC_10 1 "CSC1#" 2 "CSC2#" 3 "CSC3#" 4 "CSC4#" 5 "CSC5#" 6 "CSC6#" 7 "CSC7#" 8 "CSC8#" ;
VAL_ 2333343563 S2A_TRDM_ThrmlRnwyFltCseMsk_11 1 "bit0:欠压和过温" 2 "bit1:欠压和温升速率过大" 4 "bit2:欠压和温差过大" 8 "bit3:温升速率过大和过温" 16 "bit4:温升速率过大和温差过大" 32 "bit5:采样线掉线和过温" 64 "bit6:采样线掉线和温升速率过大" 128 "bit7采样线掉线和温差过大" ;
VAL_ 2333343563 S2A_TRDM_ThrmlRnwyFltCSC_11 1 "CSC1#" 2 "CSC2#" 3 "CSC3#" 4 "CSC4#" 5 "CSC5#" 6 "CSC6#" 7 "CSC7#" 8 "CSC8#" ;
VAL_ 2333343564 S2A_TRDM_ThrmlRnwyFltCseMsk_12 1 "bit0:欠压和过温" 2 "bit1:欠压和温升速率过大" 4 "bit2:欠压和温差过大" 8 "bit3:温升速率过大和过温" 16 "bit4:温升速率过大和温差过大" 32 "bit5:采样线掉线和过温" 64 "bit6:采样线掉线和温升速率过大" 128 "bit7采样线掉线和温差过大" ;
VAL_ 2333343564 S2A_TRDM_ThrmlRnwyFltCSC_12 1 "CSC1#" 2 "CSC2#" 3 "CSC3#" 4 "CSC4#" 5 "CSC5#" 6 "CSC6#" 7 "CSC7#" 8 "CSC8#" ;
VAL_ 2333343565 S2A_TRDM_ThrmlRnwyFltCseMsk_13 1 "bit0:欠压和过温" 2 "bit1:欠压和温升速率过大" 4 "bit2:欠压和温差过大" 8 "bit3:温升速率过大和过温" 16 "bit4:温升速率过大和温差过大" 32 "bit5:采样线掉线和过温" 64 "bit6:采样线掉线和温升速率过大" 128 "bit7采样线掉线和温差过大" ;
VAL_ 2333343565 S2A_TRDM_ThrmlRnwyFltCSC_13 1 "CSC1#" 2 "CSC2#" 3 "CSC3#" 4 "CSC4#" 5 "CSC5#" 6 "CSC6#" 7 "CSC7#" 8 "CSC8#" ;
VAL_ 2333343566 S2A_TRDM_ThrmlRnwyFltCseMsk_14 1 "bit0:欠压和过温" 2 "bit1:欠压和温升速率过大" 4 "bit2:欠压和温差过大" 8 "bit3:温升速率过大和过温" 16 "bit4:温升速率过大和温差过大" 32 "bit5:采样线掉线和过温" 64 "bit6:采样线掉线和温升速率过大" 128 "bit7采样线掉线和温差过大" ;
VAL_ 2333343566 S2A_TRDM_ThrmlRnwyFltCSC_14 1 "CSC1#" 2 "CSC2#" 3 "CSC3#" 4 "CSC4#" 5 "CSC5#" 6 "CSC6#" 7 "CSC7#" 8 "CSC8#" ;
VAL_ 2333343567 S2A_TRDM_ThrmlRnwyFltCseMsk_15 1 "bit0:欠压和过温" 2 "bit1:欠压和温升速率过大" 4 "bit2:欠压和温差过大" 8 "bit3:温升速率过大和过温" 16 "bit4:温升速率过大和温差过大" 32 "bit5:采样线掉线和过温" 64 "bit6:采样线掉线和温升速率过大" 128 "bit7采样线掉线和温差过大" ;
VAL_ 2333343567 S2A_TRDM_ThrmlRnwyFltCSC_15 1 "CSC1#" 2 "CSC2#" 3 "CSC3#" 4 "CSC4#" 5 "CSC5#" 6 "CSC6#" 7 "CSC7#" 8 "CSC8#" ;
VAL_ 2333343568 S2A_TRDM_ThrmlRnwyFltCseMsk_16 1 "bit0:欠压和过温" 2 "bit1:欠压和温升速率过大" 4 "bit2:欠压和温差过大" 8 "bit3:温升速率过大和过温" 16 "bit4:温升速率过大和温差过大" 32 "bit5:采样线掉线和过温" 64 "bit6:采样线掉线和温升速率过大" 128 "bit7采样线掉线和温差过大" ;
VAL_ 2333343568 S2A_TRDM_ThrmlRnwyFltCSC_16 1 "CSC1#" 2 "CSC2#" 3 "CSC3#" 4 "CSC4#" 5 "CSC5#" 6 "CSC6#" 7 "CSC7#" 8 "CSC8#" ;
VAL_ 2333343569 S2A_TRDM_ThrmlRnwyFltCseMsk_17 1 "bit0:欠压和过温" 2 "bit1:欠压和温升速率过大" 4 "bit2:欠压和温差过大" 8 "bit3:温升速率过大和过温" 16 "bit4:温升速率过大和温差过大" 32 "bit5:采样线掉线和过温" 64 "bit6:采样线掉线和温升速率过大" 128 "bit7采样线掉线和温差过大" ;
VAL_ 2333343569 S2A_TRDM_ThrmlRnwyFltCSC_17 1 "CSC1#" 2 "CSC2#" 3 "CSC3#" 4 "CSC4#" 5 "CSC5#" 6 "CSC6#" 7 "CSC7#" 8 "CSC8#" ;
VAL_ 2333343570 S2A_TRDM_ThrmlRnwyFltCseMsk_18 1 "bit0:欠压和过温" 2 "bit1:欠压和温升速率过大" 4 "bit2:欠压和温差过大" 8 "bit3:温升速率过大和过温" 16 "bit4:温升速率过大和温差过大" 32 "bit5:采样线掉线和过温" 64 "bit6:采样线掉线和温升速率过大" 128 "bit7采样线掉线和温差过大" ;
VAL_ 2333343570 S2A_TRDM_ThrmlRnwyFltCSC_18 1 "CSC1#" 2 "CSC2#" 3 "CSC3#" 4 "CSC4#" 5 "CSC5#" 6 "CSC6#" 7 "CSC7#" 8 "CSC8#" ;
VAL_ 2333343571 S2A_TRDM_ThrmlRnwyFltCseMsk_19 1 "bit0:欠压和过温" 2 "bit1:欠压和温升速率过大" 4 "bit2:欠压和温差过大" 8 "bit3:温升速率过大和过温" 16 "bit4:温升速率过大和温差过大" 32 "bit5:采样线掉线和过温" 64 "bit6:采样线掉线和温升速率过大" 128 "bit7采样线掉线和温差过大" ;
VAL_ 2333343571 S2A_TRDM_ThrmlRnwyFltCSC_19 1 "CSC1#" 2 "CSC2#" 3 "CSC3#" 4 "CSC4#" 5 "CSC5#" 6 "CSC6#" 7 "CSC7#" 8 "CSC8#" ;
VAL_ 2333343572 S2A_TRDM_ThrmlRnwyFltCseMsk_20 1 "bit0:欠压和过温" 2 "bit1:欠压和温升速率过大" 4 "bit2:欠压和温差过大" 8 "bit3:温升速率过大和过温" 16 "bit4:温升速率过大和温差过大" 32 "bit5:采样线掉线和过温" 64 "bit6:采样线掉线和温升速率过大" 128 "bit7采样线掉线和温差过大" ;
VAL_ 2333343572 S2A_TRDM_ThrmlRnwyFltCSC_20 1 "CSC1#" 2 "CSC2#" 3 "CSC3#" 4 "CSC4#" 5 "CSC5#" 6 "CSC6#" 7 "CSC7#" 8 "CSC8#" ;
VAL_ 2333343573 S2A_TRDM_ThrmlRnwyFltCseMsk_21 1 "bit0:欠压和过温" 2 "bit1:欠压和温升速率过大" 4 "bit2:欠压和温差过大" 8 "bit3:温升速率过大和过温" 16 "bit4:温升速率过大和温差过大" 32 "bit5:采样线掉线和过温" 64 "bit6:采样线掉线和温升速率过大" 128 "bit7采样线掉线和温差过大" ;
VAL_ 2333343573 S2A_TRDM_ThrmlRnwyFltCSC_21 1 "CSC1#" 2 "CSC2#" 3 "CSC3#" 4 "CSC4#" 5 "CSC5#" 6 "CSC6#" 7 "CSC7#" 8 "CSC8#" ;
VAL_ 2333343574 S2A_TRDM_ThrmlRnwyFltCseMsk_22 1 "bit0:欠压和过温" 2 "bit1:欠压和温升速率过大" 4 "bit2:欠压和温差过大" 8 "bit3:温升速率过大和过温" 16 "bit4:温升速率过大和温差过大" 32 "bit5:采样线掉线和过温" 64 "bit6:采样线掉线和温升速率过大" 128 "bit7采样线掉线和温差过大" ;
VAL_ 2333343574 S2A_TRDM_ThrmlRnwyFltCSC_22 1 "CSC1#" 2 "CSC2#" 3 "CSC3#" 4 "CSC4#" 5 "CSC5#" 6 "CSC6#" 7 "CSC7#" 8 "CSC8#" ;
VAL_ 2333343575 S2A_TRDM_ThrmlRnwyFltCseMsk_23 1 "bit0:欠压和过温" 2 "bit1:欠压和温升速率过大" 4 "bit2:欠压和温差过大" 8 "bit3:温升速率过大和过温" 16 "bit4:温升速率过大和温差过大" 32 "bit5:采样线掉线和过温" 64 "bit6:采样线掉线和温升速率过大" 128 "bit7采样线掉线和温差过大" ;
VAL_ 2333343575 S2A_TRDM_ThrmlRnwyFltCSC_23 1 "CSC1#" 2 "CSC2#" 3 "CSC3#" 4 "CSC4#" 5 "CSC5#" 6 "CSC6#" 7 "CSC7#" 8 "CSC8#" ;
VAL_ 2333343576 S2A_TRDM_ThrmlRnwyFltCseMsk_24 1 "bit0:欠压和过温" 2 "bit1:欠压和温升速率过大" 4 "bit2:欠压和温差过大" 8 "bit3:温升速率过大和过温" 16 "bit4:温升速率过大和温差过大" 32 "bit5:采样线掉线和过温" 64 "bit6:采样线掉线和温升速率过大" 128 "bit7采样线掉线和温差过大" ;
VAL_ 2333343576 S2A_TRDM_ThrmlRnwyFltCSC_24 1 "CSC1#" 2 "CSC2#" 3 "CSC3#" 4 "CSC4#" 5 "CSC5#" 6 "CSC6#" 7 "CSC7#" 8 "CSC8#" ;
VAL_ 2333343577 S2A_TRDM_ThrmlRnwyFltCseMsk_25 1 "bit0:欠压和过温" 2 "bit1:欠压和温升速率过大" 4 "bit2:欠压和温差过大" 8 "bit3:温升速率过大和过温" 16 "bit4:温升速率过大和温差过大" 32 "bit5:采样线掉线和过温" 64 "bit6:采样线掉线和温升速率过大" 128 "bit7采样线掉线和温差过大" ;
VAL_ 2333343577 S2A_TRDM_ThrmlRnwyFltCSC_25 1 "CSC1#" 2 "CSC2#" 3 "CSC3#" 4 "CSC4#" 5 "CSC5#" 6 "CSC6#" 7 "CSC7#" 8 "CSC8#" ;
VAL_ 2333343578 S2A_TRDM_ThrmlRnwyFltCseMsk_26 1 "bit0:欠压和过温" 2 "bit1:欠压和温升速率过大" 4 "bit2:欠压和温差过大" 8 "bit3:温升速率过大和过温" 16 "bit4:温升速率过大和温差过大" 32 "bit5:采样线掉线和过温" 64 "bit6:采样线掉线和温升速率过大" 128 "bit7采样线掉线和温差过大" ;
VAL_ 2333343578 S2A_TRDM_ThrmlRnwyFltCSC_26 1 "CSC1#" 2 "CSC2#" 3 "CSC3#" 4 "CSC4#" 5 "CSC5#" 6 "CSC6#" 7 "CSC7#" 8 "CSC8#" ;
VAL_ 2333343579 S2A_TRDM_ThrmlRnwyFltCseMsk_27 1 "bit0:欠压和过温" 2 "bit1:欠压和温升速率过大" 4 "bit2:欠压和温差过大" 8 "bit3:温升速率过大和过温" 16 "bit4:温升速率过大和温差过大" 32 "bit5:采样线掉线和过温" 64 "bit6:采样线掉线和温升速率过大" 128 "bit7采样线掉线和温差过大" ;
VAL_ 2333343579 S2A_TRDM_ThrmlRnwyFltCSC_27 1 "CSC1#" 2 "CSC2#" 3 "CSC3#" 4 "CSC4#" 5 "CSC5#" 6 "CSC6#" 7 "CSC7#" 8 "CSC8#" ;
VAL_ 2333343580 S2A_TRDM_ThrmlRnwyFltCseMsk_28 1 "bit0:欠压和过温" 2 "bit1:欠压和温升速率过大" 4 "bit2:欠压和温差过大" 8 "bit3:温升速率过大和过温" 16 "bit4:温升速率过大和温差过大" 32 "bit5:采样线掉线和过温" 64 "bit6:采样线掉线和温升速率过大" 128 "bit7采样线掉线和温差过大" ;
VAL_ 2333343580 S2A_TRDM_ThrmlRnwyFltCSC_28 1 "CSC1#" 2 "CSC2#" 3 "CSC3#" 4 "CSC4#" 5 "CSC5#" 6 "CSC6#" 7 "CSC7#" 8 "CSC8#" ;
VAL_ 2333343581 S2A_TRDM_ThrmlRnwyFltCseMsk_29 1 "bit0:欠压和过温" 2 "bit1:欠压和温升速率过大" 4 "bit2:欠压和温差过大" 8 "bit3:温升速率过大和过温" 16 "bit4:温升速率过大和温差过大" 32 "bit5:采样线掉线和过温" 64 "bit6:采样线掉线和温升速率过大" 128 "bit7采样线掉线和温差过大" ;
VAL_ 2333343581 S2A_TRDM_ThrmlRnwyFltCSC_29 1 "CSC1#" 2 "CSC2#" 3 "CSC3#" 4 "CSC4#" 5 "CSC5#" 6 "CSC6#" 7 "CSC7#" 8 "CSC8#" ;
VAL_ 2333343582 S2A_TRDM_ThrmlRnwyFltCseMsk_30 1 "bit0:欠压和过温" 2 "bit1:欠压和温升速率过大" 4 "bit2:欠压和温差过大" 8 "bit3:温升速率过大和过温" 16 "bit4:温升速率过大和温差过大" 32 "bit5:采样线掉线和过温" 64 "bit6:采样线掉线和温升速率过大" 128 "bit7采样线掉线和温差过大" ;
VAL_ 2333343582 S2A_TRDM_ThrmlRnwyFltCSC_30 1 "CSC1#" 2 "CSC2#" 3 "CSC3#" 4 "CSC4#" 5 "CSC5#" 6 "CSC6#" 7 "CSC7#" 8 "CSC8#" ;
VAL_ 2333343583 S2A_TRDM_ThrmlRnwyFltCseMsk_31 1 "bit0:欠压和过温" 2 "bit1:欠压和温升速率过大" 4 "bit2:欠压和温差过大" 8 "bit3:温升速率过大和过温" 16 "bit4:温升速率过大和温差过大" 32 "bit5:采样线掉线和过温" 64 "bit6:采样线掉线和温升速率过大" 128 "bit7采样线掉线和温差过大" ;
VAL_ 2333343583 S2A_TRDM_ThrmlRnwyFltCSC_31 1 "CSC1#" 2 "CSC2#" 3 "CSC3#" 4 "CSC4#" 5 "CSC5#" 6 "CSC6#" 7 "CSC7#" 8 "CSC8#" ;
VAL_ 2333343584 S2A_TRDM_ThrmlRnwyFltCseMsk_32 1 "bit0:欠压和过温" 2 "bit1:欠压和温升速率过大" 4 "bit2:欠压和温差过大" 8 "bit3:温升速率过大和过温" 16 "bit4:温升速率过大和温差过大" 32 "bit5:采样线掉线和过温" 64 "bit6:采样线掉线和温升速率过大" 128 "bit7采样线掉线和温差过大" ;
VAL_ 2333343584 S2A_TRDM_ThrmlRnwyFltCSC_32 1 "CSC1#" 2 "CSC2#" 3 "CSC3#" 4 "CSC4#" 5 "CSC5#" 6 "CSC6#" 7 "CSC7#" 8 "CSC8#" ;
VAL_ 2333343585 S2A_TRDM_ThrmlRnwyFltCseMsk_33 1 "bit0:欠压和过温" 2 "bit1:欠压和温升速率过大" 4 "bit2:欠压和温差过大" 8 "bit3:温升速率过大和过温" 16 "bit4:温升速率过大和温差过大" 32 "bit5:采样线掉线和过温" 64 "bit6:采样线掉线和温升速率过大" 128 "bit7采样线掉线和温差过大" ;
VAL_ 2333343585 S2A_TRDM_ThrmlRnwyFltCSC_33 1 "CSC1#" 2 "CSC2#" 3 "CSC3#" 4 "CSC4#" 5 "CSC5#" 6 "CSC6#" 7 "CSC7#" 8 "CSC8#" ;
VAL_ 2333343586 S2A_TRDM_ThrmlRnwyFltCseMsk_34 1 "bit0:欠压和过温" 2 "bit1:欠压和温升速率过大" 4 "bit2:欠压和温差过大" 8 "bit3:温升速率过大和过温" 16 "bit4:温升速率过大和温差过大" 32 "bit5:采样线掉线和过温" 64 "bit6:采样线掉线和温升速率过大" 128 "bit7采样线掉线和温差过大" ;
VAL_ 2333343586 S2A_TRDM_ThrmlRnwyFltCSC_34 1 "CSC1#" 2 "CSC2#" 3 "CSC3#" 4 "CSC4#" 5 "CSC5#" 6 "CSC6#" 7 "CSC7#" 8 "CSC8#" ;
VAL_ 2333343587 S2A_TRDM_ThrmlRnwyFltCseMsk_35 1 "bit0:欠压和过温" 2 "bit1:欠压和温升速率过大" 4 "bit2:欠压和温差过大" 8 "bit3:温升速率过大和过温" 16 "bit4:温升速率过大和温差过大" 32 "bit5:采样线掉线和过温" 64 "bit6:采样线掉线和温升速率过大" 128 "bit7采样线掉线和温差过大" ;
VAL_ 2333343587 S2A_TRDM_ThrmlRnwyFltCSC_35 1 "CSC1#" 2 "CSC2#" 3 "CSC3#" 4 "CSC4#" 5 "CSC5#" 6 "CSC6#" 7 "CSC7#" 8 "CSC8#" ;
VAL_ 2333343588 S2A_TRDM_ThrmlRnwyFltCseMsk_36 1 "bit0:欠压和过温" 2 "bit1:欠压和温升速率过大" 4 "bit2:欠压和温差过大" 8 "bit3:温升速率过大和过温" 16 "bit4:温升速率过大和温差过大" 32 "bit5:采样线掉线和过温" 64 "bit6:采样线掉线和温升速率过大" 128 "bit7采样线掉线和温差过大" ;
VAL_ 2333343588 S2A_TRDM_ThrmlRnwyFltCSC_36 1 "CSC1#" 2 "CSC2#" 3 "CSC3#" 4 "CSC4#" 5 "CSC5#" 6 "CSC6#" 7 "CSC7#" 8 "CSC8#" ;
VERSION ""

NS_ :

BS_:

BU_: MBMU PC SBMU IMM ETH DCDC LEMS

BO_ 2333343589 S2A_SUMDATA13__37: 8 SBMU
 SG_ S2A_TRDM_ThrmlRnwyFltCseMsk_37 : 0|16@1+ (1,0) [0|65535] ""  MBMU,PC
 SG_ S2A_TRDM_MaxModuleTempDegC_37 : 16|8@1+ (1,0) [0|255] ""  MBMU,PC
 SG_ S2A_TRDM_MinModuleTempDegC_37 : 24|8@1+ (1,0) [0|255] ""  MBMU,PC
 SG_ S2A_TRDM_MinCellVoltMv_37 : 32|16@1+ (1,0) [0|65535] ""  MBMU,PC
 SG_ S2A_TRDM_ThrmlRnwyFltCSC_37 : 48|8@1+ (1,0) [0|255] ""  MBMU,PC

BO_ 2333343590 S2A_SUMDATA13__38: 8 SBMU
 SG_ S2A_TRDM_ThrmlRnwyFltCseMsk_38 : 0|16@1+ (1,0) [0|65535] ""  MBMU,PC
 SG_ S2A_TRDM_MaxModuleTempDegC_38 : 16|8@1+ (1,0) [0|255] ""  MBMU,PC
 SG_ S2A_TRDM_MinModuleTempDegC_38 : 24|8@1+ (1,0) [0|255] ""  MBMU,PC
 SG_ S2A_TRDM_MinCellVoltMv_38 : 32|16@1+ (1,0) [0|65535] ""  MBMU,PC
 SG_ S2A_TRDM_ThrmlRnwyFltCSC_38 : 48|8@1+ (1,0) [0|255] ""  MBMU,PC

BO_ 2333343591 S2A_SUMDATA13__39: 8 SBMU
 SG_ S2A_TRDM_ThrmlRnwyFltCseMsk_39 : 0|16@1+ (1,0) [0|65535] ""  MBMU,PC
 SG_ S2A_TRDM_MaxModuleTempDegC_39 : 16|8@1+ (1,0) [0|255] ""  MBMU,PC
 SG_ S2A_TRDM_MinModuleTempDegC_39 : 24|8@1+ (1,0) [0|255] ""  MBMU,PC
 SG_ S2A_TRDM_MinCellVoltMv_39 : 32|16@1+ (1,0) [0|65535] ""  MBMU,PC
 SG_ S2A_TRDM_ThrmlRnwyFltCSC_39 : 48|8@1+ (1,0) [0|255] ""  MBMU,PC

BO_ 2333343592 S2A_SUMDATA13__40: 8 SBMU
 SG_ S2A_TRDM_ThrmlRnwyFltCseMsk_40 : 0|16@1+ (1,0) [0|65535] ""  MBMU,PC
 SG_ S2A_TRDM_MaxModuleTempDegC_40 : 16|8@1+ (1,0) [0|255] ""  MBMU,PC
 SG_ S2A_TRDM_MinModuleTempDegC_40 : 24|8@1+ (1,0) [0|255] ""  MBMU,PC
 SG_ S2A_TRDM_MinCellVoltMv_40 : 32|16@1+ (1,0) [0|65535] ""  MBMU,PC
 SG_ S2A_TRDM_ThrmlRnwyFltCSC_40 : 48|8@1+ (1,0) [0|255] ""  MBMU,PC

BO_ 2333343593 S2A_SUMDATA13__41: 8 SBMU
 SG_ S2A_TRDM_ThrmlRnwyFltCseMsk_41 : 0|16@1+ (1,0) [0|65535] ""  MBMU,PC
 SG_ S2A_TRDM_MaxModuleTempDegC_41 : 16|8@1+ (1,0) [0|255] ""  MBMU,PC
 SG_ S2A_TRDM_MinModuleTempDegC_41 : 24|8@1+ (1,0) [0|255] ""  MBMU,PC
 SG_ S2A_TRDM_MinCellVoltMv_41 : 32|16@1+ (1,0) [0|65535] ""  MBMU,PC
 SG_ S2A_TRDM_ThrmlRnwyFltCSC_41 : 48|8@1+ (1,0) [0|255] ""  MBMU,PC

BO_ 2333343594 S2A_SUMDATA13__42: 8 SBMU
 SG_ S2A_TRDM_ThrmlRnwyFltCseMsk_42 : 0|16@1+ (1,0) [0|65535] ""  MBMU,PC
 SG_ S2A_TRDM_MaxModuleTempDegC_42 : 16|8@1+ (1,0) [0|255] ""  MBMU,PC
 SG_ S2A_TRDM_MinModuleTempDegC_42 : 24|8@1+ (1,0) [0|255] ""  MBMU,PC
 SG_ S2A_TRDM_MinCellVoltMv_42 : 32|16@1+ (1,0) [0|65535] ""  MBMU,PC
 SG_ S2A_TRDM_ThrmlRnwyFltCSC_42 : 48|8@1+ (1,0) [0|255] ""  MBMU,PC

BO_ 2333343595 S2A_SUMDATA13__43: 8 SBMU
 SG_ S2A_TRDM_ThrmlRnwyFltCseMsk_43 : 0|16@1+ (1,0) [0|65535] ""  MBMU,PC
 SG_ S2A_TRDM_MaxModuleTempDegC_43 : 16|8@1+ (1,0) [0|255] ""  MBMU,PC
 SG_ S2A_TRDM_MinModuleTempDegC_43 : 24|8@1+ (1,0) [0|255] ""  MBMU,PC
 SG_ S2A_TRDM_MinCellVoltMv_43 : 32|16@1+ (1,0) [0|65535] ""  MBMU,PC
 SG_ S2A_TRDM_ThrmlRnwyFltCSC_43 : 48|8@1+ (1,0) [0|255] ""  MBMU,PC

BO_ 2333343596 S2A_SUMDATA13__44: 8 SBMU
 SG_ S2A_TRDM_ThrmlRnwyFltCseMsk_44 : 0|16@1+ (1,0) [0|65535] ""  MBMU,PC
 SG_ S2A_TRDM_MaxModuleTempDegC_44 : 16|8@1+ (1,0) [0|255] ""  MBMU,PC
 SG_ S2A_TRDM_MinModuleTempDegC_44 : 24|8@1+ (1,0) [0|255] ""  MBMU,PC
 SG_ S2A_TRDM_MinCellVoltMv_44 : 32|16@1+ (1,0) [0|65535] ""  MBMU,PC
 SG_ S2A_TRDM_ThrmlRnwyFltCSC_44 : 48|8@1+ (1,0) [0|255] ""  MBMU,PC

BO_ 2333343597 S2A_SUMDATA13__45: 8 SBMU
 SG_ S2A_TRDM_ThrmlRnwyFltCseMsk_45 : 0|16@1+ (1,0) [0|65535] ""  MBMU,PC
 SG_ S2A_TRDM_MaxModuleTempDegC_45 : 16|8@1+ (1,0) [0|255] ""  MBMU,PC
 SG_ S2A_TRDM_MinModuleTempDegC_45 : 24|8@1+ (1,0) [0|255] ""  MBMU,PC
 SG_ S2A_TRDM_MinCellVoltMv_45 : 32|16@1+ (1,0) [0|65535] ""  MBMU,PC
 SG_ S2A_TRDM_ThrmlRnwyFltCSC_45 : 48|8@1+ (1,0) [0|255] ""  MBMU,PC

BO_ 2333343598 S2A_SUMDATA13__46: 8 SBMU
 SG_ S2A_TRDM_ThrmlRnwyFltCseMsk_46 : 0|16@1+ (1,0) [0|65535] ""  MBMU,PC
 SG_ S2A_TRDM_MaxModuleTempDegC_46 : 16|8@1+ (1,0) [0|255] ""  MBMU,PC
 SG_ S2A_TRDM_MinModuleTempDegC_46 : 24|8@1+ (1,0) [0|255] ""  MBMU,PC
 SG_ S2A_TRDM_MinCellVoltMv_46 : 32|16@1+ (1,0) [0|65535] ""  MBMU,PC
 SG_ S2A_TRDM_ThrmlRnwyFltCSC_46 : 48|8@1+ (1,0) [0|255] ""  MBMU,PC

BO_ 2333343599 S2A_SUMDATA13__47: 8 SBMU
 SG_ S2A_TRDM_ThrmlRnwyFltCseMsk_47 : 0|16@1+ (1,0) [0|65535] ""  MBMU,PC
 SG_ S2A_TRDM_MaxModuleTempDegC_47 : 16|8@1+ (1,0) [0|255] ""  MBMU,PC
 SG_ S2A_TRDM_MinModuleTempDegC_47 : 24|8@1+ (1,0) [0|255] ""  MBMU,PC
 SG_ S2A_TRDM_MinCellVoltMv_47 : 32|16@1+ (1,0) [0|65535] ""  MBMU,PC
 SG_ S2A_TRDM_ThrmlRnwyFltCSC_47 : 48|8@1+ (1,0) [0|255] ""  MBMU,PC

BO_ 2333343600 S2A_SUMDATA13__48: 8 SBMU
 SG_ S2A_TRDM_ThrmlRnwyFltCseMsk_48 : 0|16@1+ (1,0) [0|65535] ""  MBMU,PC
 SG_ S2A_TRDM_MaxModuleTempDegC_48 : 16|8@1+ (1,0) [0|255] ""  MBMU,PC
 SG_ S2A_TRDM_MinModuleTempDegC_48 : 24|8@1+ (1,0) [0|255] ""  MBMU,PC
 SG_ S2A_TRDM_MinCellVoltMv_48 : 32|16@1+ (1,0) [0|65535] ""  MBMU,PC
 SG_ S2A_TRDM_ThrmlRnwyFltCSC_48 : 48|8@1+ (1,0) [0|255] ""  MBMU,PC

BO_ 2333343601 S2A_SUMDATA13__49: 8 SBMU
 SG_ S2A_TRDM_ThrmlRnwyFltCseMsk_49 : 0|16@1+ (1,0) [0|65535] ""  MBMU,PC
 SG_ S2A_TRDM_MaxModuleTempDegC_49 : 16|8@1+ (1,0) [0|255] ""  MBMU,PC
 SG_ S2A_TRDM_MinModuleTempDegC_49 : 24|8@1+ (1,0) [0|255] ""  MBMU,PC
 SG_ S2A_TRDM_MinCellVoltMv_49 : 32|16@1+ (1,0) [0|65535] ""  MBMU,PC
 SG_ S2A_TRDM_ThrmlRnwyFltCSC_49 : 48|8@1+ (1,0) [0|255] ""  MBMU,PC

BO_ 2333343602 S2A_SUMDATA13__50: 8 SBMU
 SG_ S2A_TRDM_ThrmlRnwyFltCseMsk_50 : 0|16@1+ (1,0) [0|65535] ""  MBMU,PC
 SG_ S2A_TRDM_MaxModuleTempDegC_50 : 16|8@1+ (1,0) [0|255] ""  MBMU,PC
 SG_ S2A_TRDM_MinModuleTempDegC_50 : 24|8@1+ (1,0) [0|255] ""  MBMU,PC
 SG_ S2A_TRDM_MinCellVoltMv_50 : 32|16@1+ (1,0) [0|65535] ""  MBMU,PC
 SG_ S2A_TRDM_ThrmlRnwyFltCSC_50 : 48|8@1+ (1,0) [0|255] ""  MBMU,PC

BO_ 2333343603 S2A_SUMDATA13__51: 8 SBMU
 SG_ S2A_TRDM_ThrmlRnwyFltCseMsk_51 : 0|16@1+ (1,0) [0|65535] ""  MBMU,PC
 SG_ S2A_TRDM_MaxModuleTempDegC_51 : 16|8@1+ (1,0) [0|255] ""  MBMU,PC
 SG_ S2A_TRDM_MinModuleTempDegC_51 : 24|8@1+ (1,0) [0|255] ""  MBMU,PC
 SG_ S2A_TRDM_MinCellVoltMv_51 : 32|16@1+ (1,0) [0|65535] ""  MBMU,PC
 SG_ S2A_TRDM_ThrmlRnwyFltCSC_51 : 48|8@1+ (1,0) [0|255] ""  MBMU,PC

BO_ 2333343604 S2A_SUMDATA13__52: 8 SBMU
 SG_ S2A_TRDM_ThrmlRnwyFltCseMsk_52 : 0|16@1+ (1,0) [0|65535] ""  MBMU,PC
 SG_ S2A_TRDM_MaxModuleTempDegC_52 : 16|8@1+ (1,0) [0|255] ""  MBMU,PC
 SG_ S2A_TRDM_MinModuleTempDegC_52 : 24|8@1+ (1,0) [0|255] ""  MBMU,PC
 SG_ S2A_TRDM_MinCellVoltMv_52 : 32|16@1+ (1,0) [0|65535] ""  MBMU,PC
 SG_ S2A_TRDM_ThrmlRnwyFltCSC_52 : 48|8@1+ (1,0) [0|255] ""  MBMU,PC

BO_ 2333343605 S2A_SUMDATA13__53: 8 SBMU
 SG_ S2A_TRDM_ThrmlRnwyFltCseMsk_53 : 0|16@1+ (1,0) [0|65535] ""  MBMU,PC
 SG_ S2A_TRDM_MaxModuleTempDegC_53 : 16|8@1+ (1,0) [0|255] ""  MBMU,PC
 SG_ S2A_TRDM_MinModuleTempDegC_53 : 24|8@1+ (1,0) [0|255] ""  MBMU,PC
 SG_ S2A_TRDM_MinCellVoltMv_53 : 32|16@1+ (1,0) [0|65535] ""  MBMU,PC
 SG_ S2A_TRDM_ThrmlRnwyFltCSC_53 : 48|8@1+ (1,0) [0|255] ""  MBMU,PC

BO_ 2333343606 S2A_SUMDATA13__54: 8 SBMU
 SG_ S2A_TRDM_ThrmlRnwyFltCseMsk_54 : 0|16@1+ (1,0) [0|65535] ""  MBMU,PC
 SG_ S2A_TRDM_MaxModuleTempDegC_54 : 16|8@1+ (1,0) [0|255] ""  MBMU,PC
 SG_ S2A_TRDM_MinModuleTempDegC_54 : 24|8@1+ (1,0) [0|255] ""  MBMU,PC
 SG_ S2A_TRDM_MinCellVoltMv_54 : 32|16@1+ (1,0) [0|65535] ""  MBMU,PC
 SG_ S2A_TRDM_ThrmlRnwyFltCSC_54 : 48|8@1+ (1,0) [0|255] ""  MBMU,PC

BO_ 2333343607 S2A_SUMDATA13__55: 8 SBMU
 SG_ S2A_TRDM_ThrmlRnwyFltCseMsk_55 : 0|16@1+ (1,0) [0|65535] ""  MBMU,PC
 SG_ S2A_TRDM_MaxModuleTempDegC_55 : 16|8@1+ (1,0) [0|255] ""  MBMU,PC
 SG_ S2A_TRDM_MinModuleTempDegC_55 : 24|8@1+ (1,0) [0|255] ""  MBMU,PC
 SG_ S2A_TRDM_MinCellVoltMv_55 : 32|16@1+ (1,0) [0|65535] ""  MBMU,PC
 SG_ S2A_TRDM_ThrmlRnwyFltCSC_55 : 48|8@1+ (1,0) [0|255] ""  MBMU,PC

BO_ 2333343608 S2A_SUMDATA13__56: 8 SBMU
 SG_ S2A_TRDM_ThrmlRnwyFltCseMsk_56 : 0|16@1+ (1,0) [0|65535] ""  MBMU,PC
 SG_ S2A_TRDM_MaxModuleTempDegC_56 : 16|8@1+ (1,0) [0|255] ""  MBMU,PC
 SG_ S2A_TRDM_MinModuleTempDegC_56 : 24|8@1+ (1,0) [0|255] ""  MBMU,PC
 SG_ S2A_TRDM_MinCellVoltMv_56 : 32|16@1+ (1,0) [0|65535] ""  MBMU,PC
 SG_ S2A_TRDM_ThrmlRnwyFltCSC_56 : 48|8@1+ (1,0) [0|255] ""  MBMU,PC

BO_ 2333343609 S2A_SUMDATA13__57: 8 SBMU
 SG_ S2A_TRDM_ThrmlRnwyFltCseMsk_57 : 0|16@1+ (1,0) [0|65535] ""  MBMU,PC
 SG_ S2A_TRDM_MaxModuleTempDegC_57 : 16|8@1+ (1,0) [0|255] ""  MBMU,PC
 SG_ S2A_TRDM_MinModuleTempDegC_57 : 24|8@1+ (1,0) [0|255] ""  MBMU,PC
 SG_ S2A_TRDM_MinCellVoltMv_57 : 32|16@1+ (1,0) [0|65535] ""  MBMU,PC
 SG_ S2A_TRDM_ThrmlRnwyFltCSC_57 : 48|8@1+ (1,0) [0|255] ""  MBMU,PC

BO_ 2333343610 S2A_SUMDATA13__58: 8 SBMU
 SG_ S2A_TRDM_ThrmlRnwyFltCseMsk_58 : 0|16@1+ (1,0) [0|65535] ""  MBMU,PC
 SG_ S2A_TRDM_MaxModuleTempDegC_58 : 16|8@1+ (1,0) [0|255] ""  MBMU,PC
 SG_ S2A_TRDM_MinModuleTempDegC_58 : 24|8@1+ (1,0) [0|255] ""  MBMU,PC
 SG_ S2A_TRDM_MinCellVoltMv_58 : 32|16@1+ (1,0) [0|65535] ""  MBMU,PC
 SG_ S2A_TRDM_ThrmlRnwyFltCSC_58 : 48|8@1+ (1,0) [0|255] ""  MBMU,PC

BO_ 2333343611 S2A_SUMDATA13__59: 8 SBMU
 SG_ S2A_TRDM_ThrmlRnwyFltCseMsk_59 : 0|16@1+ (1,0) [0|65535] ""  MBMU,PC
 SG_ S2A_TRDM_MaxModuleTempDegC_59 : 16|8@1+ (1,0) [0|255] ""  MBMU,PC
 SG_ S2A_TRDM_MinModuleTempDegC_59 : 24|8@1+ (1,0) [0|255] ""  MBMU,PC
 SG_ S2A_TRDM_MinCellVoltMv_59 : 32|16@1+ (1,0) [0|65535] ""  MBMU,PC
 SG_ S2A_TRDM_ThrmlRnwyFltCSC_59 : 48|8@1+ (1,0) [0|255] ""  MBMU,PC

BO_ 2333343612 S2A_SUMDATA13__60: 8 SBMU
 SG_ S2A_TRDM_ThrmlRnwyFltCseMsk_60 : 0|16@1+ (1,0) [0|65535] ""  MBMU,PC
 SG_ S2A_TRDM_MaxModuleTempDegC_60 : 16|8@1+ (1,0) [0|255] ""  MBMU,PC
 SG_ S2A_TRDM_MinModuleTempDegC_60 : 24|8@1+ (1,0) [0|255] ""  MBMU,PC
 SG_ S2A_TRDM_MinCellVoltMv_60 : 32|16@1+ (1,0) [0|65535] ""  MBMU,PC
 SG_ S2A_TRDM_ThrmlRnwyFltCSC_60 : 48|8@1+ (1,0) [0|255] ""  MBMU,PC

BO_ 2333343613 S2A_SUMDATA13__61: 8 SBMU
 SG_ S2A_TRDM_ThrmlRnwyFltCseMsk_61 : 0|16@1+ (1,0) [0|65535] ""  MBMU,PC
 SG_ S2A_TRDM_MaxModuleTempDegC_61 : 16|8@1+ (1,0) [0|255] ""  MBMU,PC
 SG_ S2A_TRDM_MinModuleTempDegC_61 : 24|8@1+ (1,0) [0|255] ""  MBMU,PC
 SG_ S2A_TRDM_MinCellVoltMv_61 : 32|16@1+ (1,0) [0|65535] ""  MBMU,PC
 SG_ S2A_TRDM_ThrmlRnwyFltCSC_61 : 48|8@1+ (1,0) [0|255] ""  MBMU,PC

BO_ 2333343614 S2A_SUMDATA13__62: 8 SBMU
 SG_ S2A_TRDM_ThrmlRnwyFltCseMsk_62 : 0|16@1+ (1,0) [0|65535] ""  MBMU,PC
 SG_ S2A_TRDM_MaxModuleTempDegC_62 : 16|8@1+ (1,0) [0|255] ""  MBMU,PC
 SG_ S2A_TRDM_MinModuleTempDegC_62 : 24|8@1+ (1,0) [0|255] ""  MBMU,PC
 SG_ S2A_TRDM_MinCellVoltMv_62 : 32|16@1+ (1,0) [0|65535] ""  MBMU,PC
 SG_ S2A_TRDM_ThrmlRnwyFltCSC_62 : 48|8@1+ (1,0) [0|255] ""  MBMU,PC

BO_ 2333343615 S2A_SUMDATA13__63: 8 SBMU
 SG_ S2A_TRDM_ThrmlRnwyFltCseMsk_63 : 0|16@1+ (1,0) [0|65535] ""  MBMU,PC
 SG_ S2A_TRDM_MaxModuleTempDegC_63 : 16|8@1+ (1,0) [0|255] ""  MBMU,PC
 SG_ S2A_TRDM_MinModuleTempDegC_63 : 24|8@1+ (1,0) [0|255] ""  MBMU,PC
 SG_ S2A_TRDM_MinCellVoltMv_63 : 32|16@1+ (1,0) [0|65535] ""  MBMU,PC
 SG_ S2A_TRDM_ThrmlRnwyFltCSC_63 : 48|8@1+ (1,0) [0|255] ""  MBMU,PC

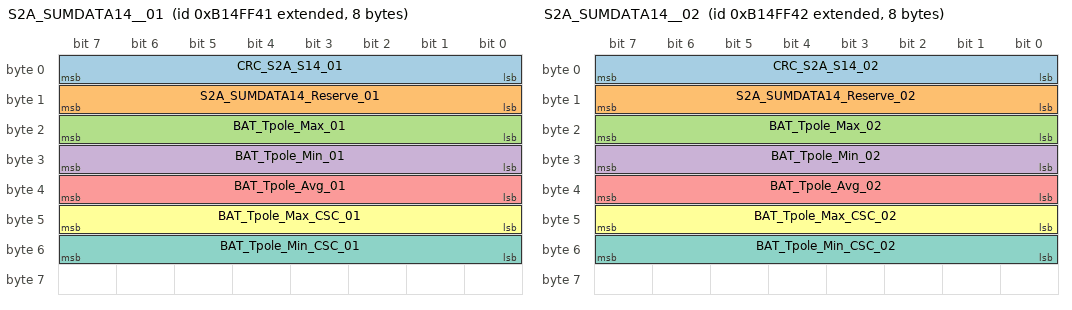
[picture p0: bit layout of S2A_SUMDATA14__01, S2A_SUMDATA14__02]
BO_ 2333409089 S2A_SUMDATA14__01: 8 SBMU
 SG_ CRC_S2A_S14_01 : 0|8@1+ (1,0) [0|255] ""  PC,MBMU
 SG_ S2A_SUMDATA14_Reserve_01 : 8|8@1+ (1,0) [0|255] ""  PC,MBMU
 SG_ BAT_Tpole_Max_01 : 16|8@1+ (1,-50) [-50|205] "℃"  PC,MBMU
 SG_ BAT_Tpole_Min_01 : 24|8@1+ (1,-50) [-50|205] "℃"  PC,MBMU
 SG_ BAT_Tpole_Avg_01 : 32|8@1+ (1,-50) [-50|205] "℃"  PC,MBMU
 SG_ BAT_Tpole_Max_CSC_01 : 40|8@1+ (1,0) [0|255] ""  PC,MBMU
 SG_ BAT_Tpole_Min_CSC_01 : 48|8@1+ (1,0) [0|255] ""  PC,MBMU

BO_ 2333409090 S2A_SUMDATA14__02: 8 SBMU
 SG_ CRC_S2A_S14_02 : 0|8@1+ (1,0) [0|255] ""  PC,MBMU
 SG_ S2A_SUMDATA14_Reserve_02 : 8|8@1+ (1,0) [0|255] ""  PC,MBMU
 SG_ BAT_Tpole_Max_02 : 16|8@1+ (1,-50) [-50|205] "℃"  PC,MBMU
 SG_ BAT_Tpole_Min_02 : 24|8@1+ (1,-50) [-50|205] "℃"  PC,MBMU
 SG_ BAT_Tpole_Avg_02 : 32|8@1+ (1,-50) [-50|205] "℃"  PC,MBMU
 SG_ BAT_Tpole_Max_CSC_02 : 40|8@1+ (1,0) [0|255] ""  PC,MBMU
 SG_ BAT_Tpole_Min_CSC_02 : 48|8@1+ (1,0) [0|255] ""  PC,MBMU

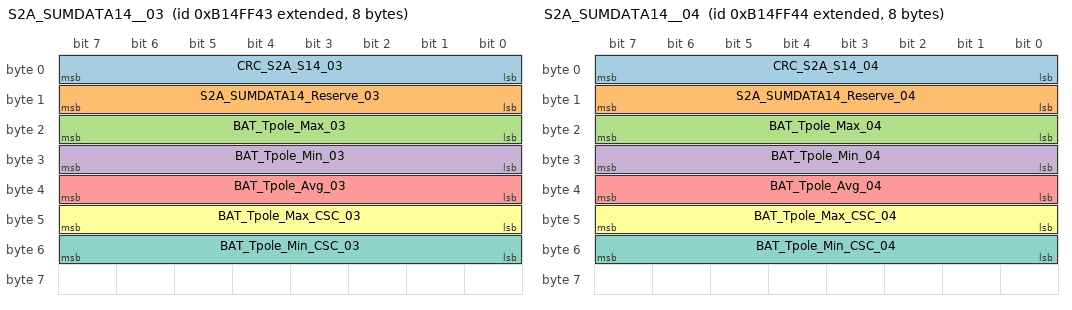
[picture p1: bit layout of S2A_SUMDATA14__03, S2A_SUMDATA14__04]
BO_ 2333409091 S2A_SUMDATA14__03: 8 SBMU
 SG_ CRC_S2A_S14_03 : 0|8@1+ (1,0) [0|255] ""  PC,MBMU
 SG_ S2A_SUMDATA14_Reserve_03 : 8|8@1+ (1,0) [0|255] ""  PC,MBMU
 SG_ BAT_Tpole_Max_03 : 16|8@1+ (1,-50) [-50|205] "℃"  PC,MBMU
 SG_ BAT_Tpole_Min_03 : 24|8@1+ (1,-50) [-50|205] "℃"  PC,MBMU
 SG_ BAT_Tpole_Avg_03 : 32|8@1+ (1,-50) [-50|205] "℃"  PC,MBMU
 SG_ BAT_Tpole_Max_CSC_03 : 40|8@1+ (1,0) [0|255] ""  PC,MBMU
 SG_ BAT_Tpole_Min_CSC_03 : 48|8@1+ (1,0) [0|255] ""  PC,MBMU

BO_ 2333409092 S2A_SUMDATA14__04: 8 SBMU
 SG_ CRC_S2A_S14_04 : 0|8@1+ (1,0) [0|255] ""  PC,MBMU
 SG_ S2A_SUMDATA14_Reserve_04 : 8|8@1+ (1,0) [0|255] ""  PC,MBMU
 SG_ BAT_Tpole_Max_04 : 16|8@1+ (1,-50) [-50|205] "℃"  PC,MBMU
 SG_ BAT_Tpole_Min_04 : 24|8@1+ (1,-50) [-50|205] "℃"  PC,MBMU
 SG_ BAT_Tpole_Avg_04 : 32|8@1+ (1,-50) [-50|205] "℃"  PC,MBMU
 SG_ BAT_Tpole_Max_CSC_04 : 40|8@1+ (1,0) [0|255] ""  PC,MBMU
 SG_ BAT_Tpole_Min_CSC_04 : 48|8@1+ (1,0) [0|255] ""  PC,MBMU

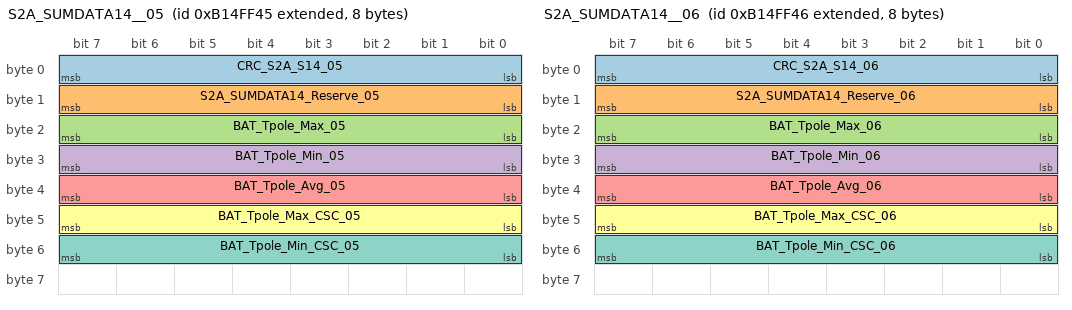
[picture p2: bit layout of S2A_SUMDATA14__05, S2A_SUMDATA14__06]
BO_ 2333409093 S2A_SUMDATA14__05: 8 SBMU
 SG_ CRC_S2A_S14_05 : 0|8@1+ (1,0) [0|255] ""  PC,MBMU
 SG_ S2A_SUMDATA14_Reserve_05 : 8|8@1+ (1,0) [0|255] ""  PC,MBMU
 SG_ BAT_Tpole_Max_05 : 16|8@1+ (1,-50) [-50|205] "℃"  PC,MBMU
 SG_ BAT_Tpole_Min_05 : 24|8@1+ (1,-50) [-50|205] "℃"  PC,MBMU
 SG_ BAT_Tpole_Avg_05 : 32|8@1+ (1,-50) [-50|205] "℃"  PC,MBMU
 SG_ BAT_Tpole_Max_CSC_05 : 40|8@1+ (1,0) [0|255] ""  PC,MBMU
 SG_ BAT_Tpole_Min_CSC_05 : 48|8@1+ (1,0) [0|255] ""  PC,MBMU

BO_ 2333409094 S2A_SUMDATA14__06: 8 SBMU
 SG_ CRC_S2A_S14_06 : 0|8@1+ (1,0) [0|255] ""  PC,MBMU
 SG_ S2A_SUMDATA14_Reserve_06 : 8|8@1+ (1,0) [0|255] ""  PC,MBMU
 SG_ BAT_Tpole_Max_06 : 16|8@1+ (1,-50) [-50|205] "℃"  PC,MBMU
 SG_ BAT_Tpole_Min_06 : 24|8@1+ (1,-50) [-50|205] "℃"  PC,MBMU
 SG_ BAT_Tpole_Avg_06 : 32|8@1+ (1,-50) [-50|205] "℃"  PC,MBMU
 SG_ BAT_Tpole_Max_CSC_06 : 40|8@1+ (1,0) [0|255] ""  PC,MBMU
 SG_ BAT_Tpole_Min_CSC_06 : 48|8@1+ (1,0) [0|255] ""  PC,MBMU

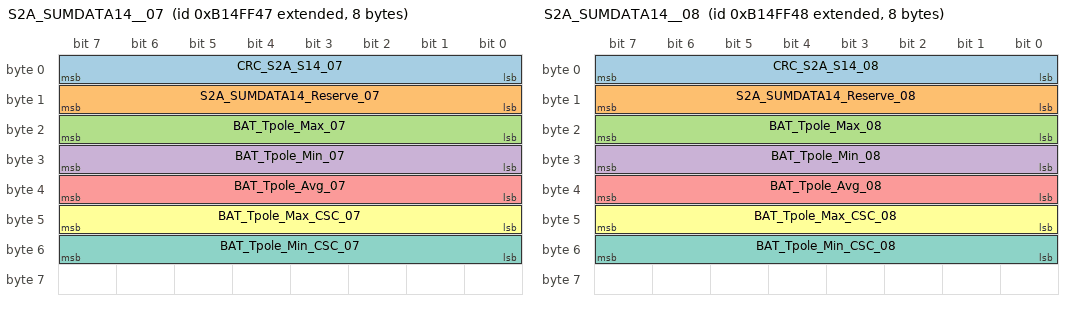
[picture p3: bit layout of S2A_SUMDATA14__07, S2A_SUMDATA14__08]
BO_ 2333409095 S2A_SUMDATA14__07: 8 SBMU
 SG_ CRC_S2A_S14_07 : 0|8@1+ (1,0) [0|255] ""  PC,MBMU
 SG_ S2A_SUMDATA14_Reserve_07 : 8|8@1+ (1,0) [0|255] ""  PC,MBMU
 SG_ BAT_Tpole_Max_07 : 16|8@1+ (1,-50) [-50|205] "℃"  PC,MBMU
 SG_ BAT_Tpole_Min_07 : 24|8@1+ (1,-50) [-50|205] "℃"  PC,MBMU
 SG_ BAT_Tpole_Avg_07 : 32|8@1+ (1,-50) [-50|205] "℃"  PC,MBMU
 SG_ BAT_Tpole_Max_CSC_07 : 40|8@1+ (1,0) [0|255] ""  PC,MBMU
 SG_ BAT_Tpole_Min_CSC_07 : 48|8@1+ (1,0) [0|255] ""  PC,MBMU

BO_ 2333409096 S2A_SUMDATA14__08: 8 SBMU
 SG_ CRC_S2A_S14_08 : 0|8@1+ (1,0) [0|255] ""  PC,MBMU
 SG_ S2A_SUMDATA14_Reserve_08 : 8|8@1+ (1,0) [0|255] ""  PC,MBMU
 SG_ BAT_Tpole_Max_08 : 16|8@1+ (1,-50) [-50|205] "℃"  PC,MBMU
 SG_ BAT_Tpole_Min_08 : 24|8@1+ (1,-50) [-50|205] "℃"  PC,MBMU
 SG_ BAT_Tpole_Avg_08 : 32|8@1+ (1,-50) [-50|205] "℃"  PC,MBMU
 SG_ BAT_Tpole_Max_CSC_08 : 40|8@1+ (1,0) [0|255] ""  PC,MBMU
 SG_ BAT_Tpole_Min_CSC_08 : 48|8@1+ (1,0) [0|255] ""  PC,MBMU

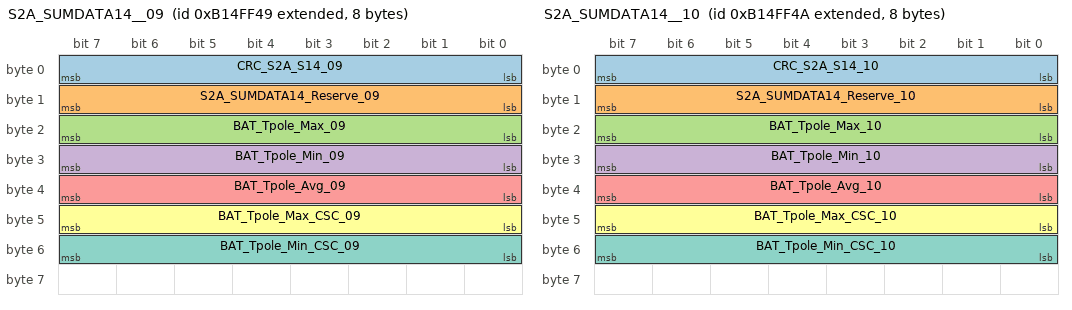
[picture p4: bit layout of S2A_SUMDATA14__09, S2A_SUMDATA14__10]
BO_ 2333409097 S2A_SUMDATA14__09: 8 SBMU
 SG_ CRC_S2A_S14_09 : 0|8@1+ (1,0) [0|255] ""  PC,MBMU
 SG_ S2A_SUMDATA14_Reserve_09 : 8|8@1+ (1,0) [0|255] ""  PC,MBMU
 SG_ BAT_Tpole_Max_09 : 16|8@1+ (1,-50) [-50|205] "℃"  PC,MBMU
 SG_ BAT_Tpole_Min_09 : 24|8@1+ (1,-50) [-50|205] "℃"  PC,MBMU
 SG_ BAT_Tpole_Avg_09 : 32|8@1+ (1,-50) [-50|205] "℃"  PC,MBMU
 SG_ BAT_Tpole_Max_CSC_09 : 40|8@1+ (1,0) [0|255] ""  PC,MBMU
 SG_ BAT_Tpole_Min_CSC_09 : 48|8@1+ (1,0) [0|255] ""  PC,MBMU

BO_ 2333409098 S2A_SUMDATA14__10: 8 SBMU
 SG_ CRC_S2A_S14_10 : 0|8@1+ (1,0) [0|255] ""  PC,MBMU
 SG_ S2A_SUMDATA14_Reserve_10 : 8|8@1+ (1,0) [0|255] ""  PC,MBMU
 SG_ BAT_Tpole_Max_10 : 16|8@1+ (1,-50) [-50|205] "℃"  PC,MBMU
 SG_ BAT_Tpole_Min_10 : 24|8@1+ (1,-50) [-50|205] "℃"  PC,MBMU
 SG_ BAT_Tpole_Avg_10 : 32|8@1+ (1,-50) [-50|205] "℃"  PC,MBMU
 SG_ BAT_Tpole_Max_CSC_10 : 40|8@1+ (1,0) [0|255] ""  PC,MBMU
 SG_ BAT_Tpole_Min_CSC_10 : 48|8@1+ (1,0) [0|255] ""  PC,MBMU

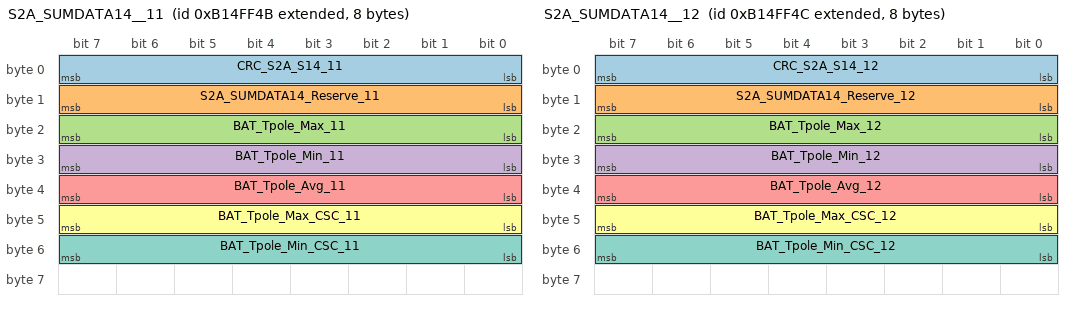
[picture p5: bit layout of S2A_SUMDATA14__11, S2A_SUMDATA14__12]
BO_ 2333409099 S2A_SUMDATA14__11: 8 SBMU
 SG_ CRC_S2A_S14_11 : 0|8@1+ (1,0) [0|255] ""  PC,MBMU
 SG_ S2A_SUMDATA14_Reserve_11 : 8|8@1+ (1,0) [0|255] ""  PC,MBMU
 SG_ BAT_Tpole_Max_11 : 16|8@1+ (1,-50) [-50|205] "℃"  PC,MBMU
 SG_ BAT_Tpole_Min_11 : 24|8@1+ (1,-50) [-50|205] "℃"  PC,MBMU
 SG_ BAT_Tpole_Avg_11 : 32|8@1+ (1,-50) [-50|205] "℃"  PC,MBMU
 SG_ BAT_Tpole_Max_CSC_11 : 40|8@1+ (1,0) [0|255] ""  PC,MBMU
 SG_ BAT_Tpole_Min_CSC_11 : 48|8@1+ (1,0) [0|255] ""  PC,MBMU

BO_ 2333409100 S2A_SUMDATA14__12: 8 SBMU
 SG_ CRC_S2A_S14_12 : 0|8@1+ (1,0) [0|255] ""  PC,MBMU
 SG_ S2A_SUMDATA14_Reserve_12 : 8|8@1+ (1,0) [0|255] ""  PC,MBMU
 SG_ BAT_Tpole_Max_12 : 16|8@1+ (1,-50) [-50|205] "℃"  PC,MBMU
 SG_ BAT_Tpole_Min_12 : 24|8@1+ (1,-50) [-50|205] "℃"  PC,MBMU
 SG_ BAT_Tpole_Avg_12 : 32|8@1+ (1,-50) [-50|205] "℃"  PC,MBMU
 SG_ BAT_Tpole_Max_CSC_12 : 40|8@1+ (1,0) [0|255] ""  PC,MBMU
 SG_ BAT_Tpole_Min_CSC_12 : 48|8@1+ (1,0) [0|255] ""  PC,MBMU

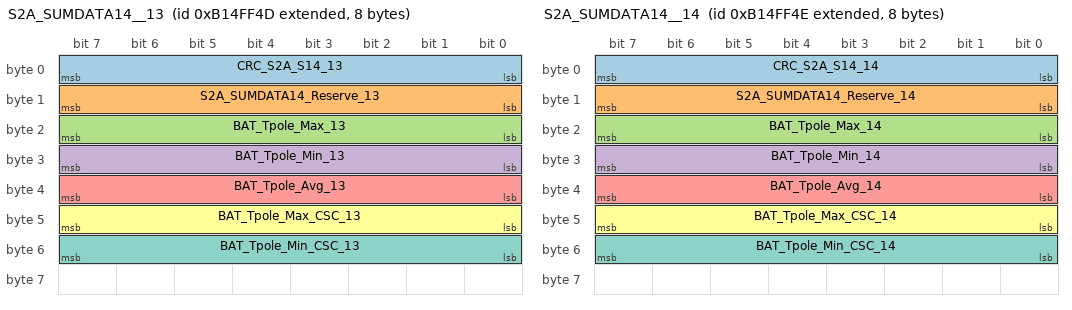
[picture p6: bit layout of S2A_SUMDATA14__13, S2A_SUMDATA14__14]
BO_ 2333409101 S2A_SUMDATA14__13: 8 SBMU
 SG_ CRC_S2A_S14_13 : 0|8@1+ (1,0) [0|255] ""  PC,MBMU
 SG_ S2A_SUMDATA14_Reserve_13 : 8|8@1+ (1,0) [0|255] ""  PC,MBMU
 SG_ BAT_Tpole_Max_13 : 16|8@1+ (1,-50) [-50|205] "℃"  PC,MBMU
 SG_ BAT_Tpole_Min_13 : 24|8@1+ (1,-50) [-50|205] "℃"  PC,MBMU
 SG_ BAT_Tpole_Avg_13 : 32|8@1+ (1,-50) [-50|205] "℃"  PC,MBMU
 SG_ BAT_Tpole_Max_CSC_13 : 40|8@1+ (1,0) [0|255] ""  PC,MBMU
 SG_ BAT_Tpole_Min_CSC_13 : 48|8@1+ (1,0) [0|255] ""  PC,MBMU

BO_ 2333409102 S2A_SUMDATA14__14: 8 SBMU
 SG_ CRC_S2A_S14_14 : 0|8@1+ (1,0) [0|255] ""  PC,MBMU
 SG_ S2A_SUMDATA14_Reserve_14 : 8|8@1+ (1,0) [0|255] ""  PC,MBMU
 SG_ BAT_Tpole_Max_14 : 16|8@1+ (1,-50) [-50|205] "℃"  PC,MBMU
 SG_ BAT_Tpole_Min_14 : 24|8@1+ (1,-50) [-50|205] "℃"  PC,MBMU
 SG_ BAT_Tpole_Avg_14 : 32|8@1+ (1,-50) [-50|205] "℃"  PC,MBMU
 SG_ BAT_Tpole_Max_CSC_14 : 40|8@1+ (1,0) [0|255] ""  PC,MBMU
 SG_ BAT_Tpole_Min_CSC_14 : 48|8@1+ (1,0) [0|255] ""  PC,MBMU

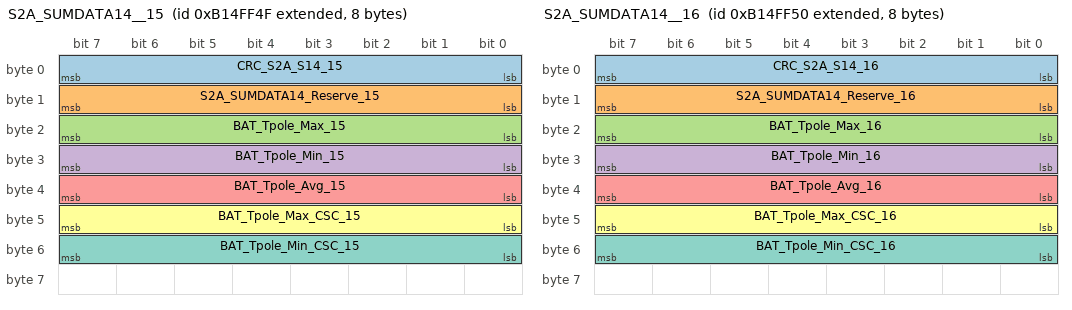
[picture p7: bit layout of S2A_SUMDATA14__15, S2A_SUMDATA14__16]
BO_ 2333409103 S2A_SUMDATA14__15: 8 SBMU
 SG_ CRC_S2A_S14_15 : 0|8@1+ (1,0) [0|255] ""  PC,MBMU
 SG_ S2A_SUMDATA14_Reserve_15 : 8|8@1+ (1,0) [0|255] ""  PC,MBMU
 SG_ BAT_Tpole_Max_15 : 16|8@1+ (1,-50) [-50|205] "℃"  PC,MBMU
 SG_ BAT_Tpole_Min_15 : 24|8@1+ (1,-50) [-50|205] "℃"  PC,MBMU
 SG_ BAT_Tpole_Avg_15 : 32|8@1+ (1,-50) [-50|205] "℃"  PC,MBMU
 SG_ BAT_Tpole_Max_CSC_15 : 40|8@1+ (1,0) [0|255] ""  PC,MBMU
 SG_ BAT_Tpole_Min_CSC_15 : 48|8@1+ (1,0) [0|255] ""  PC,MBMU

BO_ 2333409104 S2A_SUMDATA14__16: 8 SBMU
 SG_ CRC_S2A_S14_16 : 0|8@1+ (1,0) [0|255] ""  PC,MBMU
 SG_ S2A_SUMDATA14_Reserve_16 : 8|8@1+ (1,0) [0|255] ""  PC,MBMU
 SG_ BAT_Tpole_Max_16 : 16|8@1+ (1,-50) [-50|205] "℃"  PC,MBMU
 SG_ BAT_Tpole_Min_16 : 24|8@1+ (1,-50) [-50|205] "℃"  PC,MBMU
 SG_ BAT_Tpole_Avg_16 : 32|8@1+ (1,-50) [-50|205] "℃"  PC,MBMU
 SG_ BAT_Tpole_Max_CSC_16 : 40|8@1+ (1,0) [0|255] ""  PC,MBMU
 SG_ BAT_Tpole_Min_CSC_16 : 48|8@1+ (1,0) [0|255] ""  PC,MBMU

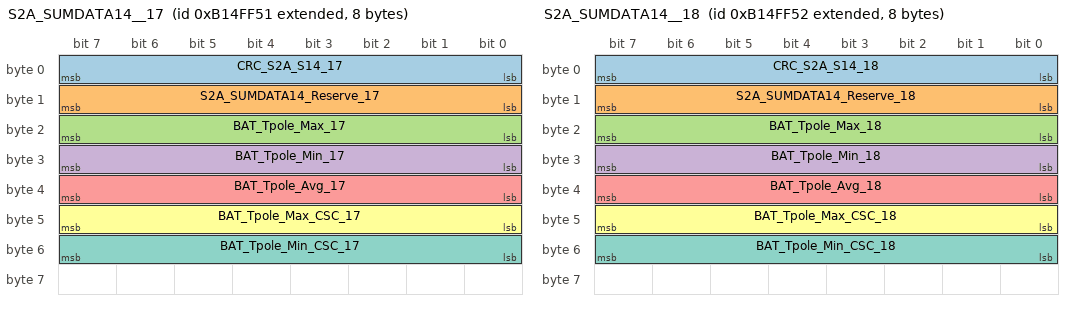
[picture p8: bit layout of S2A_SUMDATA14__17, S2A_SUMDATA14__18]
BO_ 2333409105 S2A_SUMDATA14__17: 8 SBMU
 SG_ CRC_S2A_S14_17 : 0|8@1+ (1,0) [0|255] ""  PC,MBMU
 SG_ S2A_SUMDATA14_Reserve_17 : 8|8@1+ (1,0) [0|255] ""  PC,MBMU
 SG_ BAT_Tpole_Max_17 : 16|8@1+ (1,-50) [-50|205] "℃"  PC,MBMU
 SG_ BAT_Tpole_Min_17 : 24|8@1+ (1,-50) [-50|205] "℃"  PC,MBMU
 SG_ BAT_Tpole_Avg_17 : 32|8@1+ (1,-50) [-50|205] "℃"  PC,MBMU
 SG_ BAT_Tpole_Max_CSC_17 : 40|8@1+ (1,0) [0|255] ""  PC,MBMU
 SG_ BAT_Tpole_Min_CSC_17 : 48|8@1+ (1,0) [0|255] ""  PC,MBMU

BO_ 2333409106 S2A_SUMDATA14__18: 8 SBMU
 SG_ CRC_S2A_S14_18 : 0|8@1+ (1,0) [0|255] ""  PC,MBMU
 SG_ S2A_SUMDATA14_Reserve_18 : 8|8@1+ (1,0) [0|255] ""  PC,MBMU
 SG_ BAT_Tpole_Max_18 : 16|8@1+ (1,-50) [-50|205] "℃"  PC,MBMU
 SG_ BAT_Tpole_Min_18 : 24|8@1+ (1,-50) [-50|205] "℃"  PC,MBMU
 SG_ BAT_Tpole_Avg_18 : 32|8@1+ (1,-50) [-50|205] "℃"  PC,MBMU
 SG_ BAT_Tpole_Max_CSC_18 : 40|8@1+ (1,0) [0|255] ""  PC,MBMU
 SG_ BAT_Tpole_Min_CSC_18 : 48|8@1+ (1,0) [0|255] ""  PC,MBMU

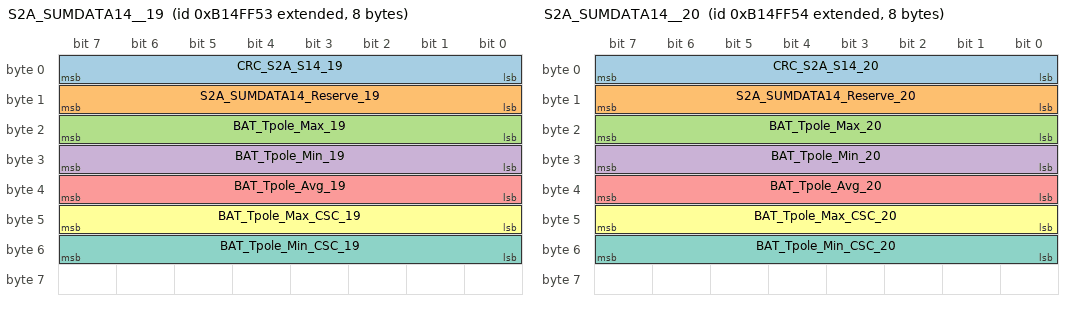
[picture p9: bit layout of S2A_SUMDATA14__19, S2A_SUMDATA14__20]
BO_ 2333409107 S2A_SUMDATA14__19: 8 SBMU
 SG_ CRC_S2A_S14_19 : 0|8@1+ (1,0) [0|255] ""  PC,MBMU
 SG_ S2A_SUMDATA14_Reserve_19 : 8|8@1+ (1,0) [0|255] ""  PC,MBMU
 SG_ BAT_Tpole_Max_19 : 16|8@1+ (1,-50) [-50|205] "℃"  PC,MBMU
 SG_ BAT_Tpole_Min_19 : 24|8@1+ (1,-50) [-50|205] "℃"  PC,MBMU
 SG_ BAT_Tpole_Avg_19 : 32|8@1+ (1,-50) [-50|205] "℃"  PC,MBMU
 SG_ BAT_Tpole_Max_CSC_19 : 40|8@1+ (1,0) [0|255] ""  PC,MBMU
 SG_ BAT_Tpole_Min_CSC_19 : 48|8@1+ (1,0) [0|255] ""  PC,MBMU

BO_ 2333409108 S2A_SUMDATA14__20: 8 SBMU
 SG_ CRC_S2A_S14_20 : 0|8@1+ (1,0) [0|255] ""  PC,MBMU
 SG_ S2A_SUMDATA14_Reserve_20 : 8|8@1+ (1,0) [0|255] ""  PC,MBMU
 SG_ BAT_Tpole_Max_20 : 16|8@1+ (1,-50) [-50|205] "℃"  PC,MBMU
 SG_ BAT_Tpole_Min_20 : 24|8@1+ (1,-50) [-50|205] "℃"  PC,MBMU
 SG_ BAT_Tpole_Avg_20 : 32|8@1+ (1,-50) [-50|205] "℃"  PC,MBMU
 SG_ BAT_Tpole_Max_CSC_20 : 40|8@1+ (1,0) [0|255] ""  PC,MBMU
 SG_ BAT_Tpole_Min_CSC_20 : 48|8@1+ (1,0) [0|255] ""  PC,MBMU

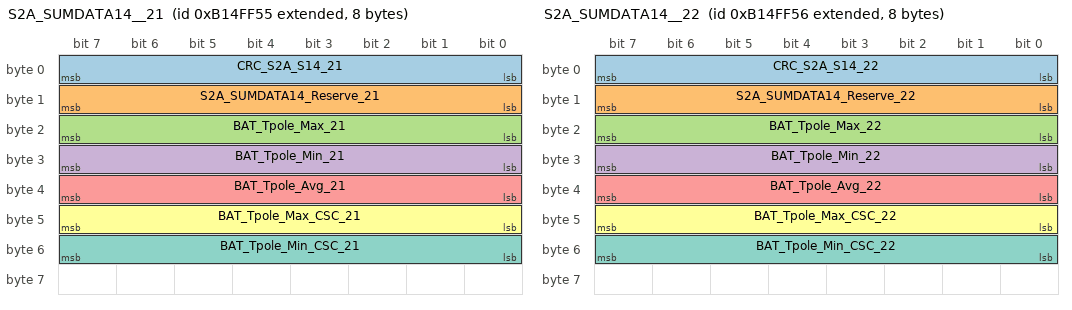
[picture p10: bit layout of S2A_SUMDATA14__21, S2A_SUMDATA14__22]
BO_ 2333409109 S2A_SUMDATA14__21: 8 SBMU
 SG_ CRC_S2A_S14_21 : 0|8@1+ (1,0) [0|255] ""  PC,MBMU
 SG_ S2A_SUMDATA14_Reserve_21 : 8|8@1+ (1,0) [0|255] ""  PC,MBMU
 SG_ BAT_Tpole_Max_21 : 16|8@1+ (1,-50) [-50|205] "℃"  PC,MBMU
 SG_ BAT_Tpole_Min_21 : 24|8@1+ (1,-50) [-50|205] "℃"  PC,MBMU
 SG_ BAT_Tpole_Avg_21 : 32|8@1+ (1,-50) [-50|205] "℃"  PC,MBMU
 SG_ BAT_Tpole_Max_CSC_21 : 40|8@1+ (1,0) [0|255] ""  PC,MBMU
 SG_ BAT_Tpole_Min_CSC_21 : 48|8@1+ (1,0) [0|255] ""  PC,MBMU

BO_ 2333409110 S2A_SUMDATA14__22: 8 SBMU
 SG_ CRC_S2A_S14_22 : 0|8@1+ (1,0) [0|255] ""  PC,MBMU
 SG_ S2A_SUMDATA14_Reserve_22 : 8|8@1+ (1,0) [0|255] ""  PC,MBMU
 SG_ BAT_Tpole_Max_22 : 16|8@1+ (1,-50) [-50|205] "℃"  PC,MBMU
 SG_ BAT_Tpole_Min_22 : 24|8@1+ (1,-50) [-50|205] "℃"  PC,MBMU
 SG_ BAT_Tpole_Avg_22 : 32|8@1+ (1,-50) [-50|205] "℃"  PC,MBMU
 SG_ BAT_Tpole_Max_CSC_22 : 40|8@1+ (1,0) [0|255] ""  PC,MBMU
 SG_ BAT_Tpole_Min_CSC_22 : 48|8@1+ (1,0) [0|255] ""  PC,MBMU

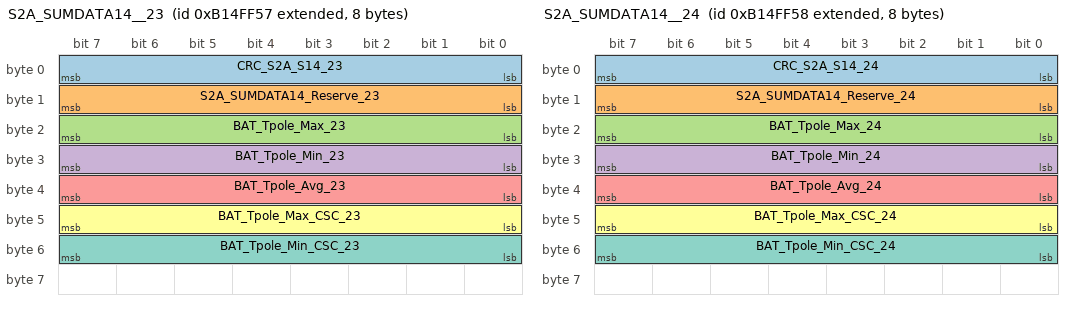
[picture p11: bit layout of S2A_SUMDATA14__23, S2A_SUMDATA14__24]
BO_ 2333409111 S2A_SUMDATA14__23: 8 SBMU
 SG_ CRC_S2A_S14_23 : 0|8@1+ (1,0) [0|255] ""  PC,MBMU
 SG_ S2A_SUMDATA14_Reserve_23 : 8|8@1+ (1,0) [0|255] ""  PC,MBMU
 SG_ BAT_Tpole_Max_23 : 16|8@1+ (1,-50) [-50|205] "℃"  PC,MBMU
 SG_ BAT_Tpole_Min_23 : 24|8@1+ (1,-50) [-50|205] "℃"  PC,MBMU
 SG_ BAT_Tpole_Avg_23 : 32|8@1+ (1,-50) [-50|205] "℃"  PC,MBMU
 SG_ BAT_Tpole_Max_CSC_23 : 40|8@1+ (1,0) [0|255] ""  PC,MBMU
 SG_ BAT_Tpole_Min_CSC_23 : 48|8@1+ (1,0) [0|255] ""  PC,MBMU

BO_ 2333409112 S2A_SUMDATA14__24: 8 SBMU
 SG_ CRC_S2A_S14_24 : 0|8@1+ (1,0) [0|255] ""  PC,MBMU
 SG_ S2A_SUMDATA14_Reserve_24 : 8|8@1+ (1,0) [0|255] ""  PC,MBMU
 SG_ BAT_Tpole_Max_24 : 16|8@1+ (1,-50) [-50|205] "℃"  PC,MBMU
 SG_ BAT_Tpole_Min_24 : 24|8@1+ (1,-50) [-50|205] "℃"  PC,MBMU
 SG_ BAT_Tpole_Avg_24 : 32|8@1+ (1,-50) [-50|205] "℃"  PC,MBMU
 SG_ BAT_Tpole_Max_CSC_24 : 40|8@1+ (1,0) [0|255] ""  PC,MBMU
 SG_ BAT_Tpole_Min_CSC_24 : 48|8@1+ (1,0) [0|255] ""  PC,MBMU

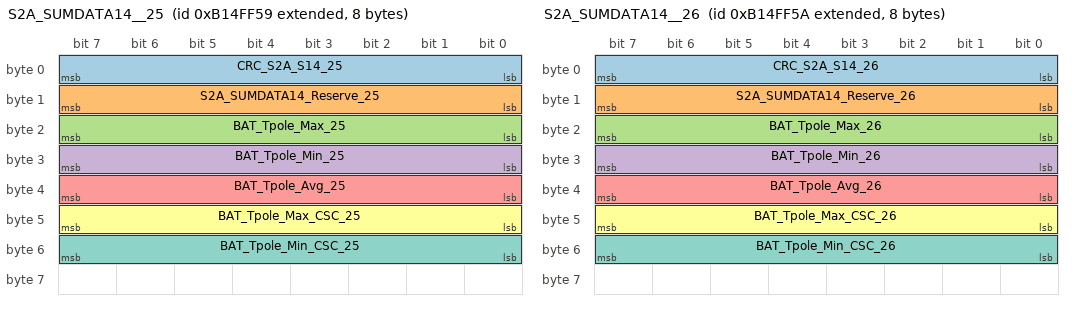
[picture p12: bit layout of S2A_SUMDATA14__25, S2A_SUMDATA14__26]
BO_ 2333409113 S2A_SUMDATA14__25: 8 SBMU
 SG_ CRC_S2A_S14_25 : 0|8@1+ (1,0) [0|255] ""  PC,MBMU
 SG_ S2A_SUMDATA14_Reserve_25 : 8|8@1+ (1,0) [0|255] ""  PC,MBMU
 SG_ BAT_Tpole_Max_25 : 16|8@1+ (1,-50) [-50|205] "℃"  PC,MBMU
 SG_ BAT_Tpole_Min_25 : 24|8@1+ (1,-50) [-50|205] "℃"  PC,MBMU
 SG_ BAT_Tpole_Avg_25 : 32|8@1+ (1,-50) [-50|205] "℃"  PC,MBMU
 SG_ BAT_Tpole_Max_CSC_25 : 40|8@1+ (1,0) [0|255] ""  PC,MBMU
 SG_ BAT_Tpole_Min_CSC_25 : 48|8@1+ (1,0) [0|255] ""  PC,MBMU

BO_ 2333409114 S2A_SUMDATA14__26: 8 SBMU
 SG_ CRC_S2A_S14_26 : 0|8@1+ (1,0) [0|255] ""  PC,MBMU
 SG_ S2A_SUMDATA14_Reserve_26 : 8|8@1+ (1,0) [0|255] ""  PC,MBMU
 SG_ BAT_Tpole_Max_26 : 16|8@1+ (1,-50) [-50|205] "℃"  PC,MBMU
 SG_ BAT_Tpole_Min_26 : 24|8@1+ (1,-50) [-50|205] "℃"  PC,MBMU
 SG_ BAT_Tpole_Avg_26 : 32|8@1+ (1,-50) [-50|205] "℃"  PC,MBMU
 SG_ BAT_Tpole_Max_CSC_26 : 40|8@1+ (1,0) [0|255] ""  PC,MBMU
 SG_ BAT_Tpole_Min_CSC_26 : 48|8@1+ (1,0) [0|255] ""  PC,MBMU

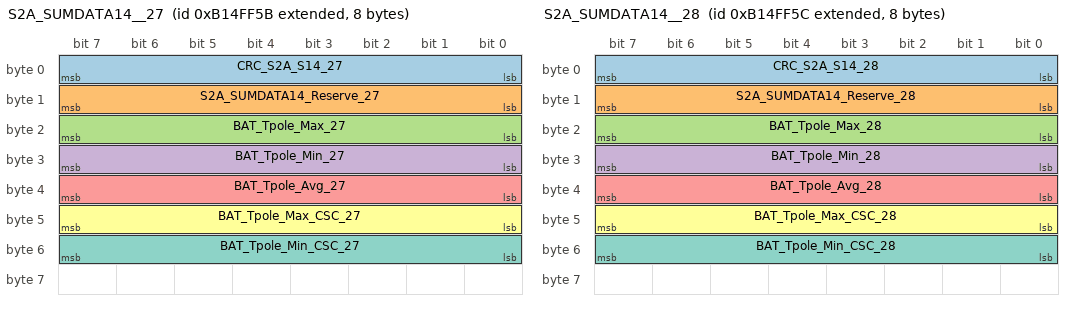
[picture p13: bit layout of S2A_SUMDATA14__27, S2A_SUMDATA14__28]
BO_ 2333409115 S2A_SUMDATA14__27: 8 SBMU
 SG_ CRC_S2A_S14_27 : 0|8@1+ (1,0) [0|255] ""  PC,MBMU
 SG_ S2A_SUMDATA14_Reserve_27 : 8|8@1+ (1,0) [0|255] ""  PC,MBMU
 SG_ BAT_Tpole_Max_27 : 16|8@1+ (1,-50) [-50|205] "℃"  PC,MBMU
 SG_ BAT_Tpole_Min_27 : 24|8@1+ (1,-50) [-50|205] "℃"  PC,MBMU
 SG_ BAT_Tpole_Avg_27 : 32|8@1+ (1,-50) [-50|205] "℃"  PC,MBMU
 SG_ BAT_Tpole_Max_CSC_27 : 40|8@1+ (1,0) [0|255] ""  PC,MBMU
 SG_ BAT_Tpole_Min_CSC_27 : 48|8@1+ (1,0) [0|255] ""  PC,MBMU

BO_ 2333409116 S2A_SUMDATA14__28: 8 SBMU
 SG_ CRC_S2A_S14_28 : 0|8@1+ (1,0) [0|255] ""  PC,MBMU
 SG_ S2A_SUMDATA14_Reserve_28 : 8|8@1+ (1,0) [0|255] ""  PC,MBMU
 SG_ BAT_Tpole_Max_28 : 16|8@1+ (1,-50) [-50|205] "℃"  PC,MBMU
 SG_ BAT_Tpole_Min_28 : 24|8@1+ (1,-50) [-50|205] "℃"  PC,MBMU
 SG_ BAT_Tpole_Avg_28 : 32|8@1+ (1,-50) [-50|205] "℃"  PC,MBMU
 SG_ BAT_Tpole_Max_CSC_28 : 40|8@1+ (1,0) [0|255] ""  PC,MBMU
 SG_ BAT_Tpole_Min_CSC_28 : 48|8@1+ (1,0) [0|255] ""  PC,MBMU

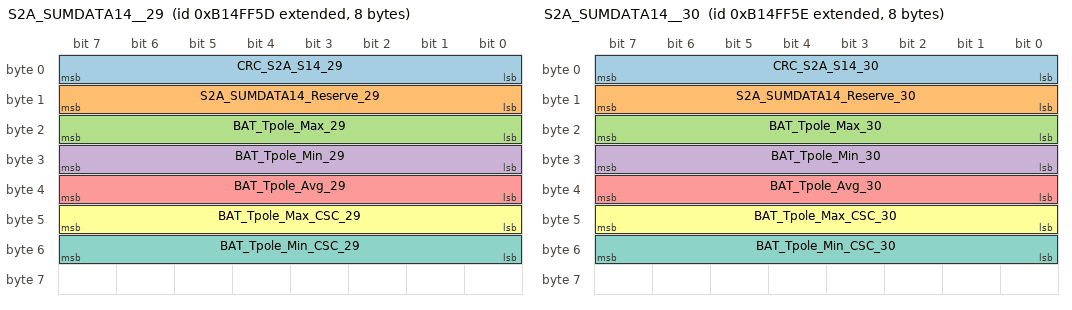
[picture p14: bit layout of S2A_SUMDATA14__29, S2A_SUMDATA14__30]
BO_ 2333409117 S2A_SUMDATA14__29: 8 SBMU
 SG_ CRC_S2A_S14_29 : 0|8@1+ (1,0) [0|255] ""  PC,MBMU
 SG_ S2A_SUMDATA14_Reserve_29 : 8|8@1+ (1,0) [0|255] ""  PC,MBMU
 SG_ BAT_Tpole_Max_29 : 16|8@1+ (1,-50) [-50|205] "℃"  PC,MBMU
 SG_ BAT_Tpole_Min_29 : 24|8@1+ (1,-50) [-50|205] "℃"  PC,MBMU
 SG_ BAT_Tpole_Avg_29 : 32|8@1+ (1,-50) [-50|205] "℃"  PC,MBMU
 SG_ BAT_Tpole_Max_CSC_29 : 40|8@1+ (1,0) [0|255] ""  PC,MBMU
 SG_ BAT_Tpole_Min_CSC_29 : 48|8@1+ (1,0) [0|255] ""  PC,MBMU

BO_ 2333409118 S2A_SUMDATA14__30: 8 SBMU
 SG_ CRC_S2A_S14_30 : 0|8@1+ (1,0) [0|255] ""  PC,MBMU
 SG_ S2A_SUMDATA14_Reserve_30 : 8|8@1+ (1,0) [0|255] ""  PC,MBMU
 SG_ BAT_Tpole_Max_30 : 16|8@1+ (1,-50) [-50|205] "℃"  PC,MBMU
 SG_ BAT_Tpole_Min_30 : 24|8@1+ (1,-50) [-50|205] "℃"  PC,MBMU
 SG_ BAT_Tpole_Avg_30 : 32|8@1+ (1,-50) [-50|205] "℃"  PC,MBMU
 SG_ BAT_Tpole_Max_CSC_30 : 40|8@1+ (1,0) [0|255] ""  PC,MBMU
 SG_ BAT_Tpole_Min_CSC_30 : 48|8@1+ (1,0) [0|255] ""  PC,MBMU

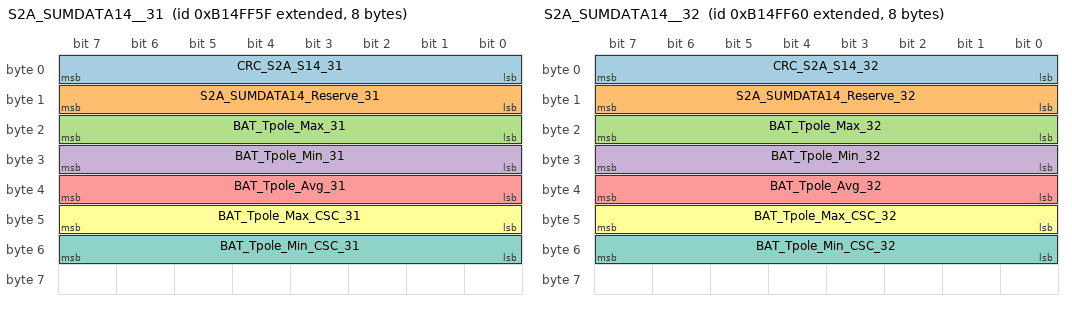
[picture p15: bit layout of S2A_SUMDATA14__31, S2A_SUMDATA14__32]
BO_ 2333409119 S2A_SUMDATA14__31: 8 SBMU
 SG_ CRC_S2A_S14_31 : 0|8@1+ (1,0) [0|255] ""  PC,MBMU
 SG_ S2A_SUMDATA14_Reserve_31 : 8|8@1+ (1,0) [0|255] ""  PC,MBMU
 SG_ BAT_Tpole_Max_31 : 16|8@1+ (1,-50) [-50|205] "℃"  PC,MBMU
 SG_ BAT_Tpole_Min_31 : 24|8@1+ (1,-50) [-50|205] "℃"  PC,MBMU
 SG_ BAT_Tpole_Avg_31 : 32|8@1+ (1,-50) [-50|205] "℃"  PC,MBMU
 SG_ BAT_Tpole_Max_CSC_31 : 40|8@1+ (1,0) [0|255] ""  PC,MBMU
 SG_ BAT_Tpole_Min_CSC_31 : 48|8@1+ (1,0) [0|255] ""  PC,MBMU

BO_ 2333409120 S2A_SUMDATA14__32: 8 SBMU
 SG_ CRC_S2A_S14_32 : 0|8@1+ (1,0) [0|255] ""  PC,MBMU
 SG_ S2A_SUMDATA14_Reserve_32 : 8|8@1+ (1,0) [0|255] ""  PC,MBMU
 SG_ BAT_Tpole_Max_32 : 16|8@1+ (1,-50) [-50|205] "℃"  PC,MBMU
 SG_ BAT_Tpole_Min_32 : 24|8@1+ (1,-50) [-50|205] "℃"  PC,MBMU
 SG_ BAT_Tpole_Avg_32 : 32|8@1+ (1,-50) [-50|205] "℃"  PC,MBMU
 SG_ BAT_Tpole_Max_CSC_32 : 40|8@1+ (1,0) [0|255] ""  PC,MBMU
 SG_ BAT_Tpole_Min_CSC_32 : 48|8@1+ (1,0) [0|255] ""  PC,MBMU

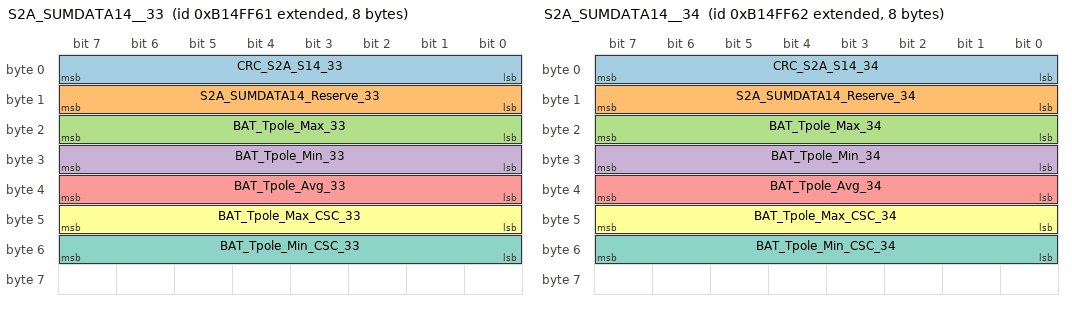
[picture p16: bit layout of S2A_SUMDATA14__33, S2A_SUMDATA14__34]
BO_ 2333409121 S2A_SUMDATA14__33: 8 SBMU
 SG_ CRC_S2A_S14_33 : 0|8@1+ (1,0) [0|255] ""  PC,MBMU
 SG_ S2A_SUMDATA14_Reserve_33 : 8|8@1+ (1,0) [0|255] ""  PC,MBMU
 SG_ BAT_Tpole_Max_33 : 16|8@1+ (1,-50) [-50|205] "℃"  PC,MBMU
 SG_ BAT_Tpole_Min_33 : 24|8@1+ (1,-50) [-50|205] "℃"  PC,MBMU
 SG_ BAT_Tpole_Avg_33 : 32|8@1+ (1,-50) [-50|205] "℃"  PC,MBMU
 SG_ BAT_Tpole_Max_CSC_33 : 40|8@1+ (1,0) [0|255] ""  PC,MBMU
 SG_ BAT_Tpole_Min_CSC_33 : 48|8@1+ (1,0) [0|255] ""  PC,MBMU

BO_ 2333409122 S2A_SUMDATA14__34: 8 SBMU
 SG_ CRC_S2A_S14_34 : 0|8@1+ (1,0) [0|255] ""  PC,MBMU
 SG_ S2A_SUMDATA14_Reserve_34 : 8|8@1+ (1,0) [0|255] ""  PC,MBMU
 SG_ BAT_Tpole_Max_34 : 16|8@1+ (1,-50) [-50|205] "℃"  PC,MBMU
 SG_ BAT_Tpole_Min_34 : 24|8@1+ (1,-50) [-50|205] "℃"  PC,MBMU
 SG_ BAT_Tpole_Avg_34 : 32|8@1+ (1,-50) [-50|205] "℃"  PC,MBMU
 SG_ BAT_Tpole_Max_CSC_34 : 40|8@1+ (1,0) [0|255] ""  PC,MBMU
 SG_ BAT_Tpole_Min_CSC_34 : 48|8@1+ (1,0) [0|255] ""  PC,MBMU

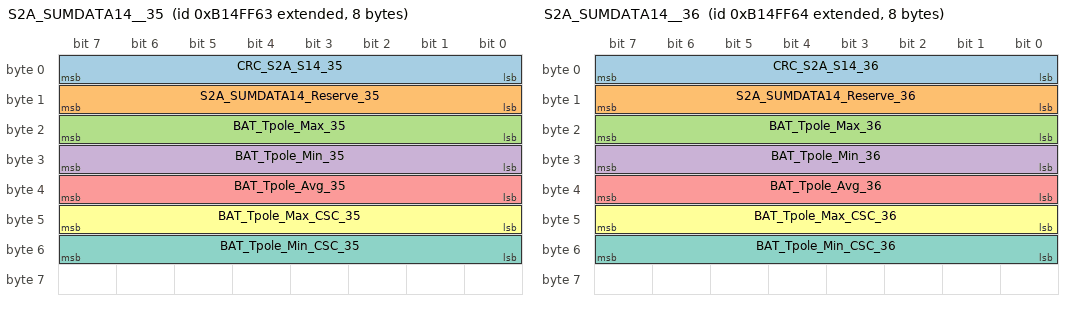
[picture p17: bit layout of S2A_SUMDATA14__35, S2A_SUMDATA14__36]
BO_ 2333409123 S2A_SUMDATA14__35: 8 SBMU
 SG_ CRC_S2A_S14_35 : 0|8@1+ (1,0) [0|255] ""  PC,MBMU
 SG_ S2A_SUMDATA14_Reserve_35 : 8|8@1+ (1,0) [0|255] ""  PC,MBMU
 SG_ BAT_Tpole_Max_35 : 16|8@1+ (1,-50) [-50|205] "℃"  PC,MBMU
 SG_ BAT_Tpole_Min_35 : 24|8@1+ (1,-50) [-50|205] "℃"  PC,MBMU
 SG_ BAT_Tpole_Avg_35 : 32|8@1+ (1,-50) [-50|205] "℃"  PC,MBMU
 SG_ BAT_Tpole_Max_CSC_35 : 40|8@1+ (1,0) [0|255] ""  PC,MBMU
 SG_ BAT_Tpole_Min_CSC_35 : 48|8@1+ (1,0) [0|255] ""  PC,MBMU

BO_ 2333409124 S2A_SUMDATA14__36: 8 SBMU
 SG_ CRC_S2A_S14_36 : 0|8@1+ (1,0) [0|255] ""  PC,MBMU
 SG_ S2A_SUMDATA14_Reserve_36 : 8|8@1+ (1,0) [0|255] ""  PC,MBMU
 SG_ BAT_Tpole_Max_36 : 16|8@1+ (1,-50) [-50|205] "℃"  PC,MBMU
 SG_ BAT_Tpole_Min_36 : 24|8@1+ (1,-50) [-50|205] "℃"  PC,MBMU
 SG_ BAT_Tpole_Avg_36 : 32|8@1+ (1,-50) [-50|205] "℃"  PC,MBMU
 SG_ BAT_Tpole_Max_CSC_36 : 40|8@1+ (1,0) [0|255] ""  PC,MBMU
 SG_ BAT_Tpole_Min_CSC_36 : 48|8@1+ (1,0) [0|255] ""  PC,MBMU

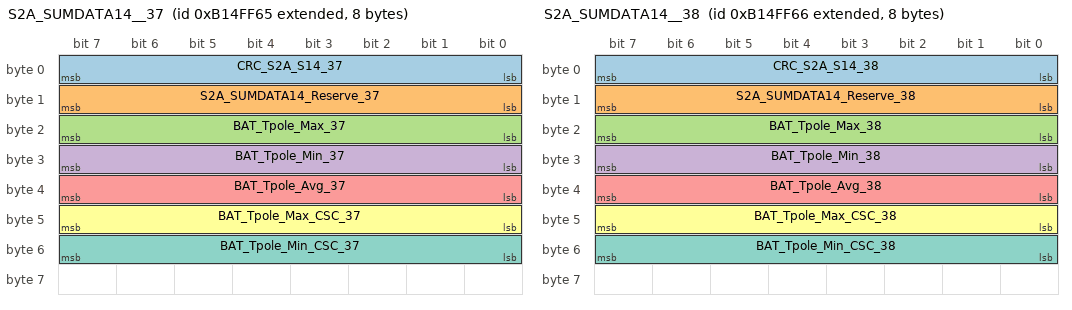
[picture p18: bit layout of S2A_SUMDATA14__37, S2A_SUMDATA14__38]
BO_ 2333409125 S2A_SUMDATA14__37: 8 SBMU
 SG_ CRC_S2A_S14_37 : 0|8@1+ (1,0) [0|255] ""  PC,MBMU
 SG_ S2A_SUMDATA14_Reserve_37 : 8|8@1+ (1,0) [0|255] ""  PC,MBMU
 SG_ BAT_Tpole_Max_37 : 16|8@1+ (1,-50) [-50|205] "℃"  PC,MBMU
 SG_ BAT_Tpole_Min_37 : 24|8@1+ (1,-50) [-50|205] "℃"  PC,MBMU
 SG_ BAT_Tpole_Avg_37 : 32|8@1+ (1,-50) [-50|205] "℃"  PC,MBMU
 SG_ BAT_Tpole_Max_CSC_37 : 40|8@1+ (1,0) [0|255] ""  PC,MBMU
 SG_ BAT_Tpole_Min_CSC_37 : 48|8@1+ (1,0) [0|255] ""  PC,MBMU

BO_ 2333409126 S2A_SUMDATA14__38: 8 SBMU
 SG_ CRC_S2A_S14_38 : 0|8@1+ (1,0) [0|255] ""  PC,MBMU
 SG_ S2A_SUMDATA14_Reserve_38 : 8|8@1+ (1,0) [0|255] ""  PC,MBMU
 SG_ BAT_Tpole_Max_38 : 16|8@1+ (1,-50) [-50|205] "℃"  PC,MBMU
 SG_ BAT_Tpole_Min_38 : 24|8@1+ (1,-50) [-50|205] "℃"  PC,MBMU
 SG_ BAT_Tpole_Avg_38 : 32|8@1+ (1,-50) [-50|205] "℃"  PC,MBMU
 SG_ BAT_Tpole_Max_CSC_38 : 40|8@1+ (1,0) [0|255] ""  PC,MBMU
 SG_ BAT_Tpole_Min_CSC_38 : 48|8@1+ (1,0) [0|255] ""  PC,MBMU

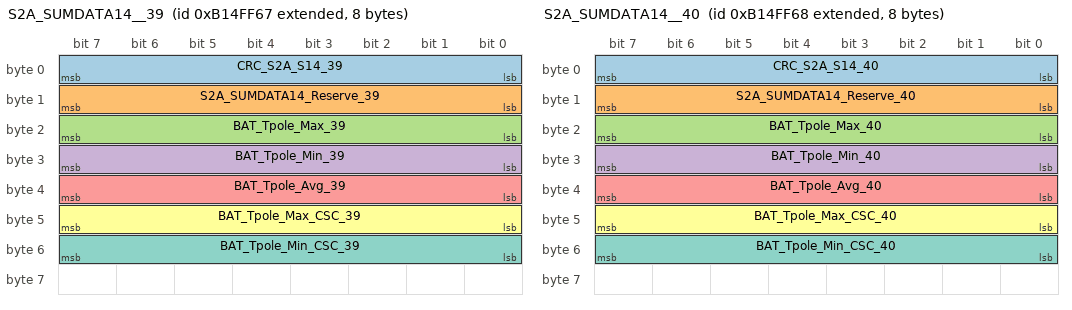
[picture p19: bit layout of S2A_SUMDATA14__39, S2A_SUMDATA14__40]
BO_ 2333409127 S2A_SUMDATA14__39: 8 SBMU
 SG_ CRC_S2A_S14_39 : 0|8@1+ (1,0) [0|255] ""  PC,MBMU
 SG_ S2A_SUMDATA14_Reserve_39 : 8|8@1+ (1,0) [0|255] ""  PC,MBMU
 SG_ BAT_Tpole_Max_39 : 16|8@1+ (1,-50) [-50|205] "℃"  PC,MBMU
 SG_ BAT_Tpole_Min_39 : 24|8@1+ (1,-50) [-50|205] "℃"  PC,MBMU
 SG_ BAT_Tpole_Avg_39 : 32|8@1+ (1,-50) [-50|205] "℃"  PC,MBMU
 SG_ BAT_Tpole_Max_CSC_39 : 40|8@1+ (1,0) [0|255] ""  PC,MBMU
 SG_ BAT_Tpole_Min_CSC_39 : 48|8@1+ (1,0) [0|255] ""  PC,MBMU

BO_ 2333409128 S2A_SUMDATA14__40: 8 SBMU
 SG_ CRC_S2A_S14_40 : 0|8@1+ (1,0) [0|255] ""  PC,MBMU
 SG_ S2A_SUMDATA14_Reserve_40 : 8|8@1+ (1,0) [0|255] ""  PC,MBMU
 SG_ BAT_Tpole_Max_40 : 16|8@1+ (1,-50) [-50|205] "℃"  PC,MBMU
 SG_ BAT_Tpole_Min_40 : 24|8@1+ (1,-50) [-50|205] "℃"  PC,MBMU
 SG_ BAT_Tpole_Avg_40 : 32|8@1+ (1,-50) [-50|205] "℃"  PC,MBMU
 SG_ BAT_Tpole_Max_CSC_40 : 40|8@1+ (1,0) [0|255] ""  PC,MBMU
 SG_ BAT_Tpole_Min_CSC_40 : 48|8@1+ (1,0) [0|255] ""  PC,MBMU

BO_ 2333409129 S2A_SUMDATA14__41: 8 SBMU
 SG_ CRC_S2A_S14_41 : 0|8@1+ (1,0) [0|255] ""  PC,MBMU
 SG_ S2A_SUMDATA14_Reserve_41 : 8|8@1+ (1,0) [0|255] ""  PC,MBMU
 SG_ BAT_Tpole_Max_41 : 16|8@1+ (1,-50) [-50|205] "℃"  PC,MBMU
 SG_ BAT_Tpole_Min_41 : 24|8@1+ (1,-50) [-50|205] "℃"  PC,MBMU
 SG_ BAT_Tpole_Avg_41 : 32|8@1+ (1,-50) [-50|205] "℃"  PC,MBMU
 SG_ BAT_Tpole_Max_CSC_41 : 40|8@1+ (1,0) [0|255] ""  PC,MBMU
 SG_ BAT_Tpole_Min_CSC_41 : 48|8@1+ (1,0) [0|255] ""  PC,MBMU

BO_ 2333409130 S2A_SUMDATA14__42: 8 SBMU
 SG_ CRC_S2A_S14_42 : 0|8@1+ (1,0) [0|255] ""  PC,MBMU
 SG_ S2A_SUMDATA14_Reserve_42 : 8|8@1+ (1,0) [0|255] ""  PC,MBMU
 SG_ BAT_Tpole_Max_42 : 16|8@1+ (1,-50) [-50|205] "℃"  PC,MBMU
 SG_ BAT_Tpole_Min_42 : 24|8@1+ (1,-50) [-50|205] "℃"  PC,MBMU
 SG_ BAT_Tpole_Avg_42 : 32|8@1+ (1,-50) [-50|205] "℃"  PC,MBMU
 SG_ BAT_Tpole_Max_CSC_42 : 40|8@1+ (1,0) [0|255] ""  PC,MBMU
 SG_ BAT_Tpole_Min_CSC_42 : 48|8@1+ (1,0) [0|255] ""  PC,MBMU

BO_ 2333409131 S2A_SUMDATA14__43: 8 SBMU
 SG_ CRC_S2A_S14_43 : 0|8@1+ (1,0) [0|255] ""  PC,MBMU
 SG_ S2A_SUMDATA14_Reserve_43 : 8|8@1+ (1,0) [0|255] ""  PC,MBMU
 SG_ BAT_Tpole_Max_43 : 16|8@1+ (1,-50) [-50|205] "℃"  PC,MBMU
 SG_ BAT_Tpole_Min_43 : 24|8@1+ (1,-50) [-50|205] "℃"  PC,MBMU
 SG_ BAT_Tpole_Avg_43 : 32|8@1+ (1,-50) [-50|205] "℃"  PC,MBMU
 SG_ BAT_Tpole_Max_CSC_43 : 40|8@1+ (1,0) [0|255] ""  PC,MBMU
 SG_ BAT_Tpole_Min_CSC_43 : 48|8@1+ (1,0) [0|255] ""  PC,MBMU

BO_ 2333409132 S2A_SUMDATA14__44: 8 SBMU
 SG_ CRC_S2A_S14_44 : 0|8@1+ (1,0) [0|255] ""  PC,MBMU
 SG_ S2A_SUMDATA14_Reserve_44 : 8|8@1+ (1,0) [0|255] ""  PC,MBMU
 SG_ BAT_Tpole_Max_44 : 16|8@1+ (1,-50) [-50|205] "℃"  PC,MBMU
 SG_ BAT_Tpole_Min_44 : 24|8@1+ (1,-50) [-50|205] "℃"  PC,MBMU
 SG_ BAT_Tpole_Avg_44 : 32|8@1+ (1,-50) [-50|205] "℃"  PC,MBMU
 SG_ BAT_Tpole_Max_CSC_44 : 40|8@1+ (1,0) [0|255] ""  PC,MBMU
 SG_ BAT_Tpole_Min_CSC_44 : 48|8@1+ (1,0) [0|255] ""  PC,MBMU

BO_ 2333409133 S2A_SUMDATA14__45: 8 SBMU
 SG_ CRC_S2A_S14_45 : 0|8@1+ (1,0) [0|255] ""  PC,MBMU
 SG_ S2A_SUMDATA14_Reserve_45 : 8|8@1+ (1,0) [0|255] ""  PC,MBMU
 SG_ BAT_Tpole_Max_45 : 16|8@1+ (1,-50) [-50|205] "℃"  PC,MBMU
 SG_ BAT_Tpole_Min_45 : 24|8@1+ (1,-50) [-50|205] "℃"  PC,MBMU
 SG_ BAT_Tpole_Avg_45 : 32|8@1+ (1,-50) [-50|205] "℃"  PC,MBMU
 SG_ BAT_Tpole_Max_CSC_45 : 40|8@1+ (1,0) [0|255] ""  PC,MBMU
 SG_ BAT_Tpole_Min_CSC_45 : 48|8@1+ (1,0) [0|255] ""  PC,MBMU

BO_ 2333409134 S2A_SUMDATA14__46: 8 SBMU
 SG_ CRC_S2A_S14_46 : 0|8@1+ (1,0) [0|255] ""  PC,MBMU
 SG_ S2A_SUMDATA14_Reserve_46 : 8|8@1+ (1,0) [0|255] ""  PC,MBMU
 SG_ BAT_Tpole_Max_46 : 16|8@1+ (1,-50) [-50|205] "℃"  PC,MBMU
 SG_ BAT_Tpole_Min_46 : 24|8@1+ (1,-50) [-50|205] "℃"  PC,MBMU
 SG_ BAT_Tpole_Avg_46 : 32|8@1+ (1,-50) [-50|205] "℃"  PC,MBMU
 SG_ BAT_Tpole_Max_CSC_46 : 40|8@1+ (1,0) [0|255] ""  PC,MBMU
 SG_ BAT_Tpole_Min_CSC_46 : 48|8@1+ (1,0) [0|255] ""  PC,MBMU

BO_ 2333409135 S2A_SUMDATA14__47: 8 SBMU
 SG_ CRC_S2A_S14_47 : 0|8@1+ (1,0) [0|255] ""  PC,MBMU
 SG_ S2A_SUMDATA14_Reserve_47 : 8|8@1+ (1,0) [0|255] ""  PC,MBMU
 SG_ BAT_Tpole_Max_47 : 16|8@1+ (1,-50) [-50|205] "℃"  PC,MBMU
 SG_ BAT_Tpole_Min_47 : 24|8@1+ (1,-50) [-50|205] "℃"  PC,MBMU
 SG_ BAT_Tpole_Avg_47 : 32|8@1+ (1,-50) [-50|205] "℃"  PC,MBMU
 SG_ BAT_Tpole_Max_CSC_47 : 40|8@1+ (1,0) [0|255] ""  PC,MBMU
 SG_ BAT_Tpole_Min_CSC_47 : 48|8@1+ (1,0) [0|255] ""  PC,MBMU

BO_ 2333409136 S2A_SUMDATA14__48: 8 SBMU
 SG_ CRC_S2A_S14_48 : 0|8@1+ (1,0) [0|255] ""  PC,MBMU
 SG_ S2A_SUMDATA14_Reserve_48 : 8|8@1+ (1,0) [0|255] ""  PC,MBMU
 SG_ BAT_Tpole_Max_48 : 16|8@1+ (1,-50) [-50|205] "℃"  PC,MBMU
 SG_ BAT_Tpole_Min_48 : 24|8@1+ (1,-50) [-50|205] "℃"  PC,MBMU
 SG_ BAT_Tpole_Avg_48 : 32|8@1+ (1,-50) [-50|205] "℃"  PC,MBMU
 SG_ BAT_Tpole_Max_CSC_48 : 40|8@1+ (1,0) [0|255] ""  PC,MBMU
 SG_ BAT_Tpole_Min_CSC_48 : 48|8@1+ (1,0) [0|255] ""  PC,MBMU

BO_ 2333409137 S2A_SUMDATA14__49: 8 SBMU
 SG_ CRC_S2A_S14_49 : 0|8@1+ (1,0) [0|255] ""  PC,MBMU
 SG_ S2A_SUMDATA14_Reserve_49 : 8|8@1+ (1,0) [0|255] ""  PC,MBMU
 SG_ BAT_Tpole_Max_49 : 16|8@1+ (1,-50) [-50|205] "℃"  PC,MBMU
 SG_ BAT_Tpole_Min_49 : 24|8@1+ (1,-50) [-50|205] "℃"  PC,MBMU
 SG_ BAT_Tpole_Avg_49 : 32|8@1+ (1,-50) [-50|205] "℃"  PC,MBMU
 SG_ BAT_Tpole_Max_CSC_49 : 40|8@1+ (1,0) [0|255] ""  PC,MBMU
 SG_ BAT_Tpole_Min_CSC_49 : 48|8@1+ (1,0) [0|255] ""  PC,MBMU

BO_ 2333409138 S2A_SUMDATA14__50: 8 SBMU
 SG_ CRC_S2A_S14_50 : 0|8@1+ (1,0) [0|255] ""  PC,MBMU
 SG_ S2A_SUMDATA14_Reserve_50 : 8|8@1+ (1,0) [0|255] ""  PC,MBMU
 SG_ BAT_Tpole_Max_50 : 16|8@1+ (1,-50) [-50|205] "℃"  PC,MBMU
 SG_ BAT_Tpole_Min_50 : 24|8@1+ (1,-50) [-50|205] "℃"  PC,MBMU
 SG_ BAT_Tpole_Avg_50 : 32|8@1+ (1,-50) [-50|205] "℃"  PC,MBMU
 SG_ BAT_Tpole_Max_CSC_50 : 40|8@1+ (1,0) [0|255] ""  PC,MBMU
 SG_ BAT_Tpole_Min_CSC_50 : 48|8@1+ (1,0) [0|255] ""  PC,MBMU

BO_ 2333409139 S2A_SUMDATA14__51: 8 SBMU
 SG_ CRC_S2A_S14_51 : 0|8@1+ (1,0) [0|255] ""  PC,MBMU
 SG_ S2A_SUMDATA14_Reserve_51 : 8|8@1+ (1,0) [0|255] ""  PC,MBMU
 SG_ BAT_Tpole_Max_51 : 16|8@1+ (1,-50) [-50|205] "℃"  PC,MBMU
 SG_ BAT_Tpole_Min_51 : 24|8@1+ (1,-50) [-50|205] "℃"  PC,MBMU
 SG_ BAT_Tpole_Avg_51 : 32|8@1+ (1,-50) [-50|205] "℃"  PC,MBMU
 SG_ BAT_Tpole_Max_CSC_51 : 40|8@1+ (1,0) [0|255] ""  PC,MBMU
 SG_ BAT_Tpole_Min_CSC_51 : 48|8@1+ (1,0) [0|255] ""  PC,MBMU

BO_ 2333409140 S2A_SUMDATA14__52: 8 SBMU
 SG_ CRC_S2A_S14_52 : 0|8@1+ (1,0) [0|255] ""  PC,MBMU
 SG_ S2A_SUMDATA14_Reserve_52 : 8|8@1+ (1,0) [0|255] ""  PC,MBMU
 SG_ BAT_Tpole_Max_52 : 16|8@1+ (1,-50) [-50|205] "℃"  PC,MBMU
 SG_ BAT_Tpole_Min_52 : 24|8@1+ (1,-50) [-50|205] "℃"  PC,MBMU
 SG_ BAT_Tpole_Avg_52 : 32|8@1+ (1,-50) [-50|205] "℃"  PC,MBMU
 SG_ BAT_Tpole_Max_CSC_52 : 40|8@1+ (1,0) [0|255] ""  PC,MBMU
 SG_ BAT_Tpole_Min_CSC_52 : 48|8@1+ (1,0) [0|255] ""  PC,MBMU

BO_ 2333409141 S2A_SUMDATA14__53: 8 SBMU
 SG_ CRC_S2A_S14_53 : 0|8@1+ (1,0) [0|255] ""  PC,MBMU
 SG_ S2A_SUMDATA14_Reserve_53 : 8|8@1+ (1,0) [0|255] ""  PC,MBMU
 SG_ BAT_Tpole_Max_53 : 16|8@1+ (1,-50) [-50|205] "℃"  PC,MBMU
 SG_ BAT_Tpole_Min_53 : 24|8@1+ (1,-50) [-50|205] "℃"  PC,MBMU
 SG_ BAT_Tpole_Avg_53 : 32|8@1+ (1,-50) [-50|205] "℃"  PC,MBMU
 SG_ BAT_Tpole_Max_CSC_53 : 40|8@1+ (1,0) [0|255] ""  PC,MBMU
 SG_ BAT_Tpole_Min_CSC_53 : 48|8@1+ (1,0) [0|255] ""  PC,MBMU

BO_ 2333409142 S2A_SUMDATA14__54: 8 SBMU
 SG_ CRC_S2A_S14_54 : 0|8@1+ (1,0) [0|255] ""  PC,MBMU
 SG_ S2A_SUMDATA14_Reserve_54 : 8|8@1+ (1,0) [0|255] ""  PC,MBMU
 SG_ BAT_Tpole_Max_54 : 16|8@1+ (1,-50) [-50|205] "℃"  PC,MBMU
 SG_ BAT_Tpole_Min_54 : 24|8@1+ (1,-50) [-50|205] "℃"  PC,MBMU
 SG_ BAT_Tpole_Avg_54 : 32|8@1+ (1,-50) [-50|205] "℃"  PC,MBMU
 SG_ BAT_Tpole_Max_CSC_54 : 40|8@1+ (1,0) [0|255] ""  PC,MBMU
 SG_ BAT_Tpole_Min_CSC_54 : 48|8@1+ (1,0) [0|255] ""  PC,MBMU

BO_ 2333409143 S2A_SUMDATA14__55: 8 SBMU
 SG_ CRC_S2A_S14_55 : 0|8@1+ (1,0) [0|255] ""  PC,MBMU
 SG_ S2A_SUMDATA14_Reserve_55 : 8|8@1+ (1,0) [0|255] ""  PC,MBMU
 SG_ BAT_Tpole_Max_55 : 16|8@1+ (1,-50) [-50|205] "℃"  PC,MBMU
 SG_ BAT_Tpole_Min_55 : 24|8@1+ (1,-50) [-50|205] "℃"  PC,MBMU
 SG_ BAT_Tpole_Avg_55 : 32|8@1+ (1,-50) [-50|205] "℃"  PC,MBMU
 SG_ BAT_Tpole_Max_CSC_55 : 40|8@1+ (1,0) [0|255] ""  PC,MBMU
 SG_ BAT_Tpole_Min_CSC_55 : 48|8@1+ (1,0) [0|255] ""  PC,MBMU

BO_ 2333409144 S2A_SUMDATA14__56: 8 SBMU
 SG_ CRC_S2A_S14_56 : 0|8@1+ (1,0) [0|255] ""  PC,MBMU
 SG_ S2A_SUMDATA14_Reserve_56 : 8|8@1+ (1,0) [0|255] ""  PC,MBMU
 SG_ BAT_Tpole_Max_56 : 16|8@1+ (1,-50) [-50|205] "℃"  PC,MBMU
 SG_ BAT_Tpole_Min_56 : 24|8@1+ (1,-50) [-50|205] "℃"  PC,MBMU
 SG_ BAT_Tpole_Avg_56 : 32|8@1+ (1,-50) [-50|205] "℃"  PC,MBMU
 SG_ BAT_Tpole_Max_CSC_56 : 40|8@1+ (1,0) [0|255] ""  PC,MBMU
 SG_ BAT_Tpole_Min_CSC_56 : 48|8@1+ (1,0) [0|255] ""  PC,MBMU

BO_ 2333409145 S2A_SUMDATA14__57: 8 SBMU
 SG_ CRC_S2A_S14_57 : 0|8@1+ (1,0) [0|255] ""  PC,MBMU
 SG_ S2A_SUMDATA14_Reserve_57 : 8|8@1+ (1,0) [0|255] ""  PC,MBMU
 SG_ BAT_Tpole_Max_57 : 16|8@1+ (1,-50) [-50|205] "℃"  PC,MBMU
 SG_ BAT_Tpole_Min_57 : 24|8@1+ (1,-50) [-50|205] "℃"  PC,MBMU
 SG_ BAT_Tpole_Avg_57 : 32|8@1+ (1,-50) [-50|205] "℃"  PC,MBMU
 SG_ BAT_Tpole_Max_CSC_57 : 40|8@1+ (1,0) [0|255] ""  PC,MBMU
 SG_ BAT_Tpole_Min_CSC_57 : 48|8@1+ (1,0) [0|255] ""  PC,MBMU

BO_ 2333409146 S2A_SUMDATA14__58: 8 SBMU
 SG_ CRC_S2A_S14_58 : 0|8@1+ (1,0) [0|255] ""  PC,MBMU
 SG_ S2A_SUMDATA14_Reserve_58 : 8|8@1+ (1,0) [0|255] ""  PC,MBMU
 SG_ BAT_Tpole_Max_58 : 16|8@1+ (1,-50) [-50|205] "℃"  PC,MBMU
 SG_ BAT_Tpole_Min_58 : 24|8@1+ (1,-50) [-50|205] "℃"  PC,MBMU
 SG_ BAT_Tpole_Avg_58 : 32|8@1+ (1,-50) [-50|205] "℃"  PC,MBMU
 SG_ BAT_Tpole_Max_CSC_58 : 40|8@1+ (1,0) [0|255] ""  PC,MBMU
 SG_ BAT_Tpole_Min_CSC_58 : 48|8@1+ (1,0) [0|255] ""  PC,MBMU

BO_ 2333409147 S2A_SUMDATA14__59: 8 SBMU
 SG_ CRC_S2A_S14_59 : 0|8@1+ (1,0) [0|255] ""  PC,MBMU
 SG_ S2A_SUMDATA14_Reserve_59 : 8|8@1+ (1,0) [0|255] ""  PC,MBMU
 SG_ BAT_Tpole_Max_59 : 16|8@1+ (1,-50) [-50|205] "℃"  PC,MBMU
 SG_ BAT_Tpole_Min_59 : 24|8@1+ (1,-50) [-50|205] "℃"  PC,MBMU
 SG_ BAT_Tpole_Avg_59 : 32|8@1+ (1,-50) [-50|205] "℃"  PC,MBMU
 SG_ BAT_Tpole_Max_CSC_59 : 40|8@1+ (1,0) [0|255] ""  PC,MBMU
 SG_ BAT_Tpole_Min_CSC_59 : 48|8@1+ (1,0) [0|255] ""  PC,MBMU

BO_ 2333409148 S2A_SUMDATA14__60: 8 SBMU
 SG_ CRC_S2A_S14_60 : 0|8@1+ (1,0) [0|255] ""  PC,MBMU
 SG_ S2A_SUMDATA14_Reserve_60 : 8|8@1+ (1,0) [0|255] ""  PC,MBMU
 SG_ BAT_Tpole_Max_60 : 16|8@1+ (1,-50) [-50|205] "℃"  PC,MBMU
 SG_ BAT_Tpole_Min_60 : 24|8@1+ (1,-50) [-50|205] "℃"  PC,MBMU
 SG_ BAT_Tpole_Avg_60 : 32|8@1+ (1,-50) [-50|205] "℃"  PC,MBMU
 SG_ BAT_Tpole_Max_CSC_60 : 40|8@1+ (1,0) [0|255] ""  PC,MBMU
 SG_ BAT_Tpole_Min_CSC_60 : 48|8@1+ (1,0) [0|255] ""  PC,MBMU

BO_ 2333409149 S2A_SUMDATA14__61: 8 SBMU
 SG_ CRC_S2A_S14_61 : 0|8@1+ (1,0) [0|255] ""  PC,MBMU
 SG_ S2A_SUMDATA14_Reserve_61 : 8|8@1+ (1,0) [0|255] ""  PC,MBMU
 SG_ BAT_Tpole_Max_61 : 16|8@1+ (1,-50) [-50|205] "℃"  PC,MBMU
 SG_ BAT_Tpole_Min_61 : 24|8@1+ (1,-50) [-50|205] "℃"  PC,MBMU
 SG_ BAT_Tpole_Avg_61 : 32|8@1+ (1,-50) [-50|205] "℃"  PC,MBMU
 SG_ BAT_Tpole_Max_CSC_61 : 40|8@1+ (1,0) [0|255] ""  PC,MBMU
 SG_ BAT_Tpole_Min_CSC_61 : 48|8@1+ (1,0) [0|255] ""  PC,MBMU

BO_ 2333409150 S2A_SUMDATA14__62: 8 SBMU
 SG_ CRC_S2A_S14_62 : 0|8@1+ (1,0) [0|255] ""  PC,MBMU
 SG_ S2A_SUMDATA14_Reserve_62 : 8|8@1+ (1,0) [0|255] ""  PC,MBMU
 SG_ BAT_Tpole_Max_62 : 16|8@1+ (1,-50) [-50|205] "℃"  PC,MBMU
 SG_ BAT_Tpole_Min_62 : 24|8@1+ (1,-50) [-50|205] "℃"  PC,MBMU
 SG_ BAT_Tpole_Avg_62 : 32|8@1+ (1,-50) [-50|205] "℃"  PC,MBMU
 SG_ BAT_Tpole_Max_CSC_62 : 40|8@1+ (1,0) [0|255] ""  PC,MBMU
 SG_ BAT_Tpole_Min_CSC_62 : 48|8@1+ (1,0) [0|255] ""  PC,MBMU

BO_ 2333409151 S2A_SUMDATA14__63: 8 SBMU
 SG_ CRC_S2A_S14_63 : 0|8@1+ (1,0) [0|255] ""  PC,MBMU
 SG_ S2A_SUMDATA14_Reserve_63 : 8|8@1+ (1,0) [0|255] ""  PC,MBMU
 SG_ BAT_Tpole_Max_63 : 16|8@1+ (1,-50) [-50|205] "℃"  PC,MBMU
 SG_ BAT_Tpole_Min_63 : 24|8@1+ (1,-50) [-50|205] "℃"  PC,MBMU
 SG_ BAT_Tpole_Avg_63 : 32|8@1+ (1,-50) [-50|205] "℃"  PC,MBMU
 SG_ BAT_Tpole_Max_CSC_63 : 40|8@1+ (1,0) [0|255] ""  PC,MBMU
 SG_ BAT_Tpole_Min_CSC_63 : 48|8@1+ (1,0) [0|255] ""  PC,MBMU

BO_ 2333474625 S2A_SUMDATA15__01: 8 SBMU
 SG_ BAT_SysremainEngy_Charge_01 : 0|16@1+ (0.1,0) [0|6553.5] "kWh"  PC,MBMU
 SG_ BAT_SysremainEngy_DisCharge_01 : 16|16@1+ (0.1,0) [0|6553.5] "kWh"  PC,MBMU
 SG_ BAT_SOE_Charge_01 : 32|10@1+ (0.1,0) [0|102.3] "%"  PC,MBMU
 SG_ BAT_SOE_DisCharge_01 : 42|10@1+ (0.1,0) [0|102.3] "%"  PC,MBMU
 SG_ S2A_StepChrMode_01 : 52|1@1+ (1,0) [0|1] ""  PC,MBMU

BO_ 2333474626 S2A_SUMDATA15__02: 8 SBMU
 SG_ BAT_SysremainEngy_Charge_02 : 0|16@1+ (0.1,0) [0|6553.5] "kWh"  PC,MBMU
 SG_ BAT_SysremainEngy_DisCharge_02 : 16|16@1+ (0.1,0) [0|6553.5] "kWh"  PC,MBMU
 SG_ BAT_SOE_Charge_02 : 32|10@1+ (0.1,0) [0|102.3] "%"  PC,MBMU
 SG_ BAT_SOE_DisCharge_02 : 42|10@1+ (0.1,0) [0|102.3] "%"  PC,MBMU
 SG_ S2A_StepChrMode_02 : 52|1@1+ (1,0) [0|1] ""  PC,MBMU

BO_ 2333474627 S2A_SUMDATA15__03: 8 SBMU
 SG_ BAT_SysremainEngy_Charge_03 : 0|16@1+ (0.1,0) [0|6553.5] "kWh"  PC,MBMU
 SG_ BAT_SysremainEngy_DisCharge_03 : 16|16@1+ (0.1,0) [0|6553.5] "kWh"  PC,MBMU
 SG_ BAT_SOE_Charge_03 : 32|10@1+ (0.1,0) [0|102.3] "%"  PC,MBMU
 SG_ BAT_SOE_DisCharge_03 : 42|10@1+ (0.1,0) [0|102.3] "%"  PC,MBMU
 SG_ S2A_StepChrMode_03 : 52|1@1+ (1,0) [0|1] ""  PC,MBMU

BO_ 2333474628 S2A_SUMDATA15__04: 8 SBMU
 SG_ BAT_SysremainEngy_Charge_04 : 0|16@1+ (0.1,0) [0|6553.5] "kWh"  PC,MBMU
 SG_ BAT_SysremainEngy_DisCharge_04 : 16|16@1+ (0.1,0) [0|6553.5] "kWh"  PC,MBMU
 SG_ BAT_SOE_Charge_04 : 32|10@1+ (0.1,0) [0|102.3] "%"  PC,MBMU
 SG_ BAT_SOE_DisCharge_04 : 42|10@1+ (0.1,0) [0|102.3] "%"  PC,MBMU
 SG_ S2A_StepChrMode_04 : 52|1@1+ (1,0) [0|1] ""  PC,MBMU

BO_ 2333474629 S2A_SUMDATA15__05: 8 SBMU
 SG_ BAT_SysremainEngy_Charge_05 : 0|16@1+ (0.1,0) [0|6553.5] "kWh"  PC,MBMU
 SG_ BAT_SysremainEngy_DisCharge_05 : 16|16@1+ (0.1,0) [0|6553.5] "kWh"  PC,MBMU
 SG_ BAT_SOE_Charge_05 : 32|10@1+ (0.1,0) [0|102.3] "%"  PC,MBMU
 SG_ BAT_SOE_DisCharge_05 : 42|10@1+ (0.1,0) [0|102.3] "%"  PC,MBMU
 SG_ S2A_StepChrMode_05 : 52|1@1+ (1,0) [0|1] ""  PC,MBMU

BO_ 2333474630 S2A_SUMDATA15__06: 8 SBMU
 SG_ BAT_SysremainEngy_Charge_06 : 0|16@1+ (0.1,0) [0|6553.5] "kWh"  PC,MBMU
 SG_ BAT_SysremainEngy_DisCharge_06 : 16|16@1+ (0.1,0) [0|6553.5] "kWh"  PC,MBMU
 SG_ BAT_SOE_Charge_06 : 32|10@1+ (0.1,0) [0|102.3] "%"  PC,MBMU
 SG_ BAT_SOE_DisCharge_06 : 42|10@1+ (0.1,0) [0|102.3] "%"  PC,MBMU
 SG_ S2A_StepChrMode_06 : 52|1@1+ (1,0) [0|1] ""  PC,MBMU

BO_ 2333474631 S2A_SUMDATA15__07: 8 SBMU
 SG_ BAT_SysremainEngy_Charge_07 : 0|16@1+ (0.1,0) [0|6553.5] "kWh"  PC,MBMU
 SG_ BAT_SysremainEngy_DisCharge_07 : 16|16@1+ (0.1,0) [0|6553.5] "kWh"  PC,MBMU
 SG_ BAT_SOE_Charge_07 : 32|10@1+ (0.1,0) [0|102.3] "%"  PC,MBMU
 SG_ BAT_SOE_DisCharge_07 : 42|10@1+ (0.1,0) [0|102.3] "%"  PC,MBMU
 SG_ S2A_StepChrMode_07 : 52|1@1+ (1,0) [0|1] ""  PC,MBMU

BO_ 2333474632 S2A_SUMDATA15__08: 8 SBMU
 SG_ BAT_SysremainEngy_Charge_08 : 0|16@1+ (0.1,0) [0|6553.5] "kWh"  PC,MBMU
 SG_ BAT_SysremainEngy_DisCharge_08 : 16|16@1+ (0.1,0) [0|6553.5] "kWh"  PC,MBMU
 SG_ BAT_SOE_Charge_08 : 32|10@1+ (0.1,0) [0|102.3] "%"  PC,MBMU
 SG_ BAT_SOE_DisCharge_08 : 42|10@1+ (0.1,0) [0|102.3] "%"  PC,MBMU
 SG_ S2A_StepChrMode_08 : 52|1@1+ (1,0) [0|1] ""  PC,MBMU

BO_ 2333474633 S2A_SUMDATA15__09: 8 SBMU
 SG_ BAT_SysremainEngy_Charge_09 : 0|16@1+ (0.1,0) [0|6553.5] "kWh"  PC,MBMU
 SG_ BAT_SysremainEngy_DisCharge_09 : 16|16@1+ (0.1,0) [0|6553.5] "kWh"  PC,MBMU
 SG_ BAT_SOE_Charge_09 : 32|10@1+ (0.1,0) [0|102.3] "%"  PC,MBMU
 SG_ BAT_SOE_DisCharge_09 : 42|10@1+ (0.1,0) [0|102.3] "%"  PC,MBMU
 SG_ S2A_StepChrMode_09 : 52|1@1+ (1,0) [0|1] ""  PC,MBMU

BO_ 2333474634 S2A_SUMDATA15__10: 8 SBMU
 SG_ BAT_SysremainEngy_Charge_10 : 0|16@1+ (0.1,0) [0|6553.5] "kWh"  PC,MBMU
 SG_ BAT_SysremainEngy_DisCharge_10 : 16|16@1+ (0.1,0) [0|6553.5] "kWh"  PC,MBMU
 SG_ BAT_SOE_Charge_10 : 32|10@1+ (0.1,0) [0|102.3] "%"  PC,MBMU
 SG_ BAT_SOE_DisCharge_10 : 42|10@1+ (0.1,0) [0|102.3] "%"  PC,MBMU
 SG_ S2A_StepChrMode_10 : 52|1@1+ (1,0) [0|1] ""  PC,MBMU

BO_ 2333474635 S2A_SUMDATA15__11: 8 SBMU
 SG_ BAT_SysremainEngy_Charge_11 : 0|16@1+ (0.1,0) [0|6553.5] "kWh"  PC,MBMU
 SG_ BAT_SysremainEngy_DisCharge_11 : 16|16@1+ (0.1,0) [0|6553.5] "kWh"  PC,MBMU
 SG_ BAT_SOE_Charge_11 : 32|10@1+ (0.1,0) [0|102.3] "%"  PC,MBMU
 SG_ BAT_SOE_DisCharge_11 : 42|10@1+ (0.1,0) [0|102.3] "%"  PC,MBMU
 SG_ S2A_StepChrMode_11 : 52|1@1+ (1,0) [0|1] ""  PC,MBMU

BO_ 2333474636 S2A_SUMDATA15__12: 8 SBMU
 SG_ BAT_SysremainEngy_Charge_12 : 0|16@1+ (0.1,0) [0|6553.5] "kWh"  PC,MBMU
 SG_ BAT_SysremainEngy_DisCharge_12 : 16|16@1+ (0.1,0) [0|6553.5] "kWh"  PC,MBMU
 SG_ BAT_SOE_Charge_12 : 32|10@1+ (0.1,0) [0|102.3] "%"  PC,MBMU
 SG_ BAT_SOE_DisCharge_12 : 42|10@1+ (0.1,0) [0|102.3] "%"  PC,MBMU
 SG_ S2A_StepChrMode_12 : 52|1@1+ (1,0) [0|1] ""  PC,MBMU

BO_ 2333474637 S2A_SUMDATA15__13: 8 SBMU
 SG_ BAT_SysremainEngy_Charge_13 : 0|16@1+ (0.1,0) [0|6553.5] "kWh"  PC,MBMU
 SG_ BAT_SysremainEngy_DisCharge_13 : 16|16@1+ (0.1,0) [0|6553.5] "kWh"  PC,MBMU
 SG_ BAT_SOE_Charge_13 : 32|10@1+ (0.1,0) [0|102.3] "%"  PC,MBMU
 SG_ BAT_SOE_DisCharge_13 : 42|10@1+ (0.1,0) [0|102.3] "%"  PC,MBMU
 SG_ S2A_StepChrMode_13 : 52|1@1+ (1,0) [0|1] ""  PC,MBMU

BO_ 2333474638 S2A_SUMDATA15__14: 8 SBMU
 SG_ BAT_SysremainEngy_Charge_14 : 0|16@1+ (0.1,0) [0|6553.5] "kWh"  PC,MBMU
 SG_ BAT_SysremainEngy_DisCharge_14 : 16|16@1+ (0.1,0) [0|6553.5] "kWh"  PC,MBMU
 SG_ BAT_SOE_Charge_14 : 32|10@1+ (0.1,0) [0|102.3] "%"  PC,MBMU
 SG_ BAT_SOE_DisCharge_14 : 42|10@1+ (0.1,0) [0|102.3] "%"  PC,MBMU
 SG_ S2A_StepChrMode_14 : 52|1@1+ (1,0) [0|1] ""  PC,MBMU

BO_ 2333474639 S2A_SUMDATA15__15: 8 SBMU
 SG_ BAT_SysremainEngy_Charge_15 : 0|16@1+ (0.1,0) [0|6553.5] "kWh"  PC,MBMU
 SG_ BAT_SysremainEngy_DisCharge_15 : 16|16@1+ (0.1,0) [0|6553.5] "kWh"  PC,MBMU
 SG_ BAT_SOE_Charge_15 : 32|10@1+ (0.1,0) [0|102.3] "%"  PC,MBMU
 SG_ BAT_SOE_DisCharge_15 : 42|10@1+ (0.1,0) [0|102.3] "%"  PC,MBMU
 SG_ S2A_StepChrMode_15 : 52|1@1+ (1,0) [0|1] ""  PC,MBMU

BO_ 2333474640 S2A_SUMDATA15__16: 8 SBMU
 SG_ BAT_SysremainEngy_Charge_16 : 0|16@1+ (0.1,0) [0|6553.5] "kWh"  PC,MBMU
 SG_ BAT_SysremainEngy_DisCharge_16 : 16|16@1+ (0.1,0) [0|6553.5] "kWh"  PC,MBMU
 SG_ BAT_SOE_Charge_16 : 32|10@1+ (0.1,0) [0|102.3] "%"  PC,MBMU
 SG_ BAT_SOE_DisCharge_16 : 42|10@1+ (0.1,0) [0|102.3] "%"  PC,MBMU
 SG_ S2A_StepChrMode_16 : 52|1@1+ (1,0) [0|1] ""  PC,MBMU

BO_ 2333474641 S2A_SUMDATA15__17: 8 SBMU
 SG_ BAT_SysremainEngy_Charge_17 : 0|16@1+ (0.1,0) [0|6553.5] "kWh"  PC,MBMU
 SG_ BAT_SysremainEngy_DisCharge_17 : 16|16@1+ (0.1,0) [0|6553.5] "kWh"  PC,MBMU
 SG_ BAT_SOE_Charge_17 : 32|10@1+ (0.1,0) [0|102.3] "%"  PC,MBMU
 SG_ BAT_SOE_DisCharge_17 : 42|10@1+ (0.1,0) [0|102.3] "%"  PC,MBMU
 SG_ S2A_StepChrMode_17 : 52|1@1+ (1,0) [0|1] ""  PC,MBMU

BO_ 2333474642 S2A_SUMDATA15__18: 8 SBMU
 SG_ BAT_SysremainEngy_Charge_18 : 0|16@1+ (0.1,0) [0|6553.5] "kWh"  PC,MBMU
 SG_ BAT_SysremainEngy_DisCharge_18 : 16|16@1+ (0.1,0) [0|6553.5] "kWh"  PC,MBMU
 SG_ BAT_SOE_Charge_18 : 32|10@1+ (0.1,0) [0|102.3] "%"  PC,MBMU
 SG_ BAT_SOE_DisCharge_18 : 42|10@1+ (0.1,0) [0|102.3] "%"  PC,MBMU
 SG_ S2A_StepChrMode_18 : 52|1@1+ (1,0) [0|1] ""  PC,MBMU

BO_ 2333474643 S2A_SUMDATA15__19: 8 SBMU
 SG_ BAT_SysremainEngy_Charge_19 : 0|16@1+ (0.1,0) [0|6553.5] "kWh"  PC,MBMU
 SG_ BAT_SysremainEngy_DisCharge_19 : 16|16@1+ (0.1,0) [0|6553.5] "kWh"  PC,MBMU
 SG_ BAT_SOE_Charge_19 : 32|10@1+ (0.1,0) [0|102.3] "%"  PC,MBMU
 SG_ BAT_SOE_DisCharge_19 : 42|10@1+ (0.1,0) [0|102.3] "%"  PC,MBMU
 SG_ S2A_StepChrMode_19 : 52|1@1+ (1,0) [0|1] ""  PC,MBMU

BO_ 2333474644 S2A_SUMDATA15__20: 8 SBMU
 SG_ BAT_SysremainEngy_Charge_20 : 0|16@1+ (0.1,0) [0|6553.5] "kWh"  PC,MBMU
 SG_ BAT_SysremainEngy_DisCharge_20 : 16|16@1+ (0.1,0) [0|6553.5] "kWh"  PC,MBMU
 SG_ BAT_SOE_Charge_20 : 32|10@1+ (0.1,0) [0|102.3] "%"  PC,MBMU
 SG_ BAT_SOE_DisCharge_20 : 42|10@1+ (0.1,0) [0|102.3] "%"  PC,MBMU
 SG_ S2A_StepChrMode_20 : 52|1@1+ (1,0) [0|1] ""  PC,MBMU

BO_ 2333474645 S2A_SUMDATA15__21: 8 SBMU
 SG_ BAT_SysremainEngy_Charge_21 : 0|16@1+ (0.1,0) [0|6553.5] "kWh"  PC,MBMU
 SG_ BAT_SysremainEngy_DisCharge_21 : 16|16@1+ (0.1,0) [0|6553.5] "kWh"  PC,MBMU
 SG_ BAT_SOE_Charge_21 : 32|10@1+ (0.1,0) [0|102.3] "%"  PC,MBMU
 SG_ BAT_SOE_DisCharge_21 : 42|10@1+ (0.1,0) [0|102.3] "%"  PC,MBMU
 SG_ S2A_StepChrMode_21 : 52|1@1+ (1,0) [0|1] ""  PC,MBMU

BO_ 2333474646 S2A_SUMDATA15__22: 8 SBMU
 SG_ BAT_SysremainEngy_Charge_22 : 0|16@1+ (0.1,0) [0|6553.5] "kWh"  PC,MBMU
 SG_ BAT_SysremainEngy_DisCharge_22 : 16|16@1+ (0.1,0) [0|6553.5] "kWh"  PC,MBMU
 SG_ BAT_SOE_Charge_22 : 32|10@1+ (0.1,0) [0|102.3] "%"  PC,MBMU
 SG_ BAT_SOE_DisCharge_22 : 42|10@1+ (0.1,0) [0|102.3] "%"  PC,MBMU
 SG_ S2A_StepChrMode_22 : 52|1@1+ (1,0) [0|1] ""  PC,MBMU

BO_ 2333474647 S2A_SUMDATA15__23: 8 SBMU
 SG_ BAT_SysremainEngy_Charge_23 : 0|16@1+ (0.1,0) [0|6553.5] "kWh"  PC,MBMU
 SG_ BAT_SysremainEngy_DisCharge_23 : 16|16@1+ (0.1,0) [0|6553.5] "kWh"  PC,MBMU
 SG_ BAT_SOE_Charge_23 : 32|10@1+ (0.1,0) [0|102.3] "%"  PC,MBMU
 SG_ BAT_SOE_DisCharge_23 : 42|10@1+ (0.1,0) [0|102.3] "%"  PC,MBMU
 SG_ S2A_StepChrMode_23 : 52|1@1+ (1,0) [0|1] ""  PC,MBMU

BO_ 2333474648 S2A_SUMDATA15__24: 8 SBMU
 SG_ BAT_SysremainEngy_Charge_24 : 0|16@1+ (0.1,0) [0|6553.5] "kWh"  PC,MBMU
 SG_ BAT_SysremainEngy_DisCharge_24 : 16|16@1+ (0.1,0) [0|6553.5] "kWh"  PC,MBMU
 SG_ BAT_SOE_Charge_24 : 32|10@1+ (0.1,0) [0|102.3] "%"  PC,MBMU
 SG_ BAT_SOE_DisCharge_24 : 42|10@1+ (0.1,0) [0|102.3] "%"  PC,MBMU
 SG_ S2A_StepChrMode_24 : 52|1@1+ (1,0) [0|1] ""  PC,MBMU

BO_ 2333474649 S2A_SUMDATA15__25: 8 SBMU
 SG_ BAT_SysremainEngy_Charge_25 : 0|16@1+ (0.1,0) [0|6553.5] "kWh"  PC,MBMU
 SG_ BAT_SysremainEngy_DisCharge_25 : 16|16@1+ (0.1,0) [0|6553.5] "kWh"  PC,MBMU
 SG_ BAT_SOE_Charge_25 : 32|10@1+ (0.1,0) [0|102.3] "%"  PC,MBMU
 SG_ BAT_SOE_DisCharge_25 : 42|10@1+ (0.1,0) [0|102.3] "%"  PC,MBMU
 SG_ S2A_StepChrMode_25 : 52|1@1+ (1,0) [0|1] ""  PC,MBMU

BO_ 2333474650 S2A_SUMDATA15__26: 8 SBMU
 SG_ BAT_SysremainEngy_Charge_26 : 0|16@1+ (0.1,0) [0|6553.5] "kWh"  PC,MBMU
 SG_ BAT_SysremainEngy_DisCharge_26 : 16|16@1+ (0.1,0) [0|6553.5] "kWh"  PC,MBMU
 SG_ BAT_SOE_Charge_26 : 32|10@1+ (0.1,0) [0|102.3] "%"  PC,MBMU
 SG_ BAT_SOE_DisCharge_26 : 42|10@1+ (0.1,0) [0|102.3] "%"  PC,MBMU
 SG_ S2A_StepChrMode_26 : 52|1@1+ (1,0) [0|1] ""  PC,MBMU

BO_ 2333474651 S2A_SUMDATA15__27: 8 SBMU
 SG_ BAT_SysremainEngy_Charge_27 : 0|16@1+ (0.1,0) [0|6553.5] "kWh"  PC,MBMU
 SG_ BAT_SysremainEngy_DisCharge_27 : 16|16@1+ (0.1,0) [0|6553.5] "kWh"  PC,MBMU
 SG_ BAT_SOE_Charge_27 : 32|10@1+ (0.1,0) [0|102.3] "%"  PC,MBMU
 SG_ BAT_SOE_DisCharge_27 : 42|10@1+ (0.1,0) [0|102.3] "%"  PC,MBMU
 SG_ S2A_StepChrMode_27 : 52|1@1+ (1,0) [0|1] ""  PC,MBMU

BO_ 2333474652 S2A_SUMDATA15__28: 8 SBMU
 SG_ BAT_SysremainEngy_Charge_28 : 0|16@1+ (0.1,0) [0|6553.5] "kWh"  PC,MBMU
 SG_ BAT_SysremainEngy_DisCharge_28 : 16|16@1+ (0.1,0) [0|6553.5] "kWh"  PC,MBMU
 SG_ BAT_SOE_Charge_28 : 32|10@1+ (0.1,0) [0|102.3] "%"  PC,MBMU
 SG_ BAT_SOE_DisCharge_28 : 42|10@1+ (0.1,0) [0|102.3] "%"  PC,MBMU
 SG_ S2A_StepChrMode_28 : 52|1@1+ (1,0) [0|1] ""  PC,MBMU

BO_ 2333474653 S2A_SUMDATA15__29: 8 SBMU
 SG_ BAT_SysremainEngy_Charge_29 : 0|16@1+ (0.1,0) [0|6553.5] "kWh"  PC,MBMU
 SG_ BAT_SysremainEngy_DisCharge_29 : 16|16@1+ (0.1,0) [0|6553.5] "kWh"  PC,MBMU
 SG_ BAT_SOE_Charge_29 : 32|10@1+ (0.1,0) [0|102.3] "%"  PC,MBMU
 SG_ BAT_SOE_DisCharge_29 : 42|10@1+ (0.1,0) [0|102.3] "%"  PC,MBMU
 SG_ S2A_StepChrMode_29 : 52|1@1+ (1,0) [0|1] ""  PC,MBMU

BO_ 2333474654 S2A_SUMDATA15__30: 8 SBMU
 SG_ BAT_SysremainEngy_Charge_30 : 0|16@1+ (0.1,0) [0|6553.5] "kWh"  PC,MBMU
 SG_ BAT_SysremainEngy_DisCharge_30 : 16|16@1+ (0.1,0) [0|6553.5] "kWh"  PC,MBMU
 SG_ BAT_SOE_Charge_30 : 32|10@1+ (0.1,0) [0|102.3] "%"  PC,MBMU
 SG_ BAT_SOE_DisCharge_30 : 42|10@1+ (0.1,0) [0|102.3] "%"  PC,MBMU
 SG_ S2A_StepChrMode_30 : 52|1@1+ (1,0) [0|1] ""  PC,MBMU

BO_ 2333474655 S2A_SUMDATA15__31: 8 SBMU
 SG_ BAT_SysremainEngy_Charge_31 : 0|16@1+ (0.1,0) [0|6553.5] "kWh"  PC,MBMU
 SG_ BAT_SysremainEngy_DisCharge_31 : 16|16@1+ (0.1,0) [0|6553.5] "kWh"  PC,MBMU
 SG_ BAT_SOE_Charge_31 : 32|10@1+ (0.1,0) [0|102.3] "%"  PC,MBMU
 SG_ BAT_SOE_DisCharge_31 : 42|10@1+ (0.1,0) [0|102.3] "%"  PC,MBMU
 SG_ S2A_StepChrMode_31 : 52|1@1+ (1,0) [0|1] ""  PC,MBMU

BO_ 2333474656 S2A_SUMDATA15__32: 8 SBMU
 SG_ BAT_SysremainEngy_Charge_32 : 0|16@1+ (0.1,0) [0|6553.5] "kWh"  PC,MBMU
 SG_ BAT_SysremainEngy_DisCharge_32 : 16|16@1+ (0.1,0) [0|6553.5] "kWh"  PC,MBMU
 SG_ BAT_SOE_Charge_32 : 32|10@1+ (0.1,0) [0|102.3] "%"  PC,MBMU
 SG_ BAT_SOE_DisCharge_32 : 42|10@1+ (0.1,0) [0|102.3] "%"  PC,MBMU
 SG_ S2A_StepChrMode_32 : 52|1@1+ (1,0) [0|1] ""  PC,MBMU

BO_ 2333474657 S2A_SUMDATA15__33: 8 SBMU
 SG_ BAT_SysremainEngy_Charge_33 : 0|16@1+ (0.1,0) [0|6553.5] "kWh"  PC,MBMU
 SG_ BAT_SysremainEngy_DisCharge_33 : 16|16@1+ (0.1,0) [0|6553.5] "kWh"  PC,MBMU
 SG_ BAT_SOE_Charge_33 : 32|10@1+ (0.1,0) [0|102.3] "%"  PC,MBMU
 SG_ BAT_SOE_DisCharge_33 : 42|10@1+ (0.1,0) [0|102.3] "%"  PC,MBMU
 SG_ S2A_StepChrMode_33 : 52|1@1+ (1,0) [0|1] ""  PC,MBMU

BO_ 2333474658 S2A_SUMDATA15__34: 8 SBMU
 SG_ BAT_SysremainEngy_Charge_34 : 0|16@1+ (0.1,0) [0|6553.5] "kWh"  PC,MBMU
 SG_ BAT_SysremainEngy_DisCharge_34 : 16|16@1+ (0.1,0) [0|6553.5] "kWh"  PC,MBMU
 SG_ BAT_SOE_Charge_34 : 32|10@1+ (0.1,0) [0|102.3] "%"  PC,MBMU
 SG_ BAT_SOE_DisCharge_34 : 42|10@1+ (0.1,0) [0|102.3] "%"  PC,MBMU
 SG_ S2A_StepChrMode_34 : 52|1@1+ (1,0) [0|1] ""  PC,MBMU

BO_ 2333474659 S2A_SUMDATA15__35: 8 SBMU
 SG_ BAT_SysremainEngy_Charge_35 : 0|16@1+ (0.1,0) [0|6553.5] "kWh"  PC,MBMU
 SG_ BAT_SysremainEngy_DisCharge_35 : 16|16@1+ (0.1,0) [0|6553.5] "kWh"  PC,MBMU
 SG_ BAT_SOE_Charge_35 : 32|10@1+ (0.1,0) [0|102.3] "%"  PC,MBMU
 SG_ BAT_SOE_DisCharge_35 : 42|10@1+ (0.1,0) [0|102.3] "%"  PC,MBMU
 SG_ S2A_StepChrMode_35 : 52|1@1+ (1,0) [0|1] ""  PC,MBMU

BO_ 2333474660 S2A_SUMDATA15__36: 8 SBMU
 SG_ BAT_SysremainEngy_Charge_36 : 0|16@1+ (0.1,0) [0|6553.5] "kWh"  PC,MBMU
 SG_ BAT_SysremainEngy_DisCharge_36 : 16|16@1+ (0.1,0) [0|6553.5] "kWh"  PC,MBMU
 SG_ BAT_SOE_Charge_36 : 32|10@1+ (0.1,0) [0|102.3] "%"  PC,MBMU
 SG_ BAT_SOE_DisCharge_36 : 42|10@1+ (0.1,0) [0|102.3] "%"  PC,MBMU
 SG_ S2A_StepChrMode_36 : 52|1@1+ (1,0) [0|1] ""  PC,MBMU

BO_ 2333474661 S2A_SUMDATA15__37: 8 SBMU
 SG_ BAT_SysremainEngy_Charge_37 : 0|16@1+ (0.1,0) [0|6553.5] "kWh"  PC,MBMU
 SG_ BAT_SysremainEngy_DisCharge_37 : 16|16@1+ (0.1,0) [0|6553.5] "kWh"  PC,MBMU
 SG_ BAT_SOE_Charge_37 : 32|10@1+ (0.1,0) [0|102.3] "%"  PC,MBMU
 SG_ BAT_SOE_DisCharge_37 : 42|10@1+ (0.1,0) [0|102.3] "%"  PC,MBMU
 SG_ S2A_StepChrMode_37 : 52|1@1+ (1,0) [0|1] ""  PC,MBMU

BO_ 2333474662 S2A_SUMDATA15__38: 8 SBMU
 SG_ BAT_SysremainEngy_Charge_38 : 0|16@1+ (0.1,0) [0|6553.5] "kWh"  PC,MBMU
 SG_ BAT_SysremainEngy_DisCharge_38 : 16|16@1+ (0.1,0) [0|6553.5] "kWh"  PC,MBMU
 SG_ BAT_SOE_Charge_38 : 32|10@1+ (0.1,0) [0|102.3] "%"  PC,MBMU
 SG_ BAT_SOE_DisCharge_38 : 42|10@1+ (0.1,0) [0|102.3] "%"  PC,MBMU
 SG_ S2A_StepChrMode_38 : 52|1@1+ (1,0) [0|1] ""  PC,MBMU

BO_ 2333474663 S2A_SUMDATA15__39: 8 SBMU
 SG_ BAT_SysremainEngy_Charge_39 : 0|16@1+ (0.1,0) [0|6553.5] "kWh"  PC,MBMU
 SG_ BAT_SysremainEngy_DisCharge_39 : 16|16@1+ (0.1,0) [0|6553.5] "kWh"  PC,MBMU
 SG_ BAT_SOE_Charge_39 : 32|10@1+ (0.1,0) [0|102.3] "%"  PC,MBMU
 SG_ BAT_SOE_DisCharge_39 : 42|10@1+ (0.1,0) [0|102.3] "%"  PC,MBMU
 SG_ S2A_StepChrMode_39 : 52|1@1+ (1,0) [0|1] ""  PC,MBMU

BO_ 2333474664 S2A_SUMDATA15__40: 8 SBMU
 SG_ BAT_SysremainEngy_Charge_40 : 0|16@1+ (0.1,0) [0|6553.5] "kWh"  PC,MBMU
 SG_ BAT_SysremainEngy_DisCharge_40 : 16|16@1+ (0.1,0) [0|6553.5] "kWh"  PC,MBMU
 SG_ BAT_SOE_Charge_40 : 32|10@1+ (0.1,0) [0|102.3] "%"  PC,MBMU
 SG_ BAT_SOE_DisCharge_40 : 42|10@1+ (0.1,0) [0|102.3] "%"  PC,MBMU
 SG_ S2A_StepChrMode_40 : 52|1@1+ (1,0) [0|1] ""  PC,MBMU

BO_ 2333474665 S2A_SUMDATA15__41: 8 SBMU
 SG_ BAT_SysremainEngy_Charge_41 : 0|16@1+ (0.1,0) [0|6553.5] "kWh"  PC,MBMU
 SG_ BAT_SysremainEngy_DisCharge_41 : 16|16@1+ (0.1,0) [0|6553.5] "kWh"  PC,MBMU
 SG_ BAT_SOE_Charge_41 : 32|10@1+ (0.1,0) [0|102.3] "%"  PC,MBMU
 SG_ BAT_SOE_DisCharge_41 : 42|10@1+ (0.1,0) [0|102.3] "%"  PC,MBMU
 SG_ S2A_StepChrMode_41 : 52|1@1+ (1,0) [0|1] ""  PC,MBMU

BO_ 2333474666 S2A_SUMDATA15__42: 8 SBMU
 SG_ BAT_SysremainEngy_Charge_42 : 0|16@1+ (0.1,0) [0|6553.5] "kWh"  PC,MBMU
 SG_ BAT_SysremainEngy_DisCharge_42 : 16|16@1+ (0.1,0) [0|6553.5] "kWh"  PC,MBMU
 SG_ BAT_SOE_Charge_42 : 32|10@1+ (0.1,0) [0|102.3] "%"  PC,MBMU
 SG_ BAT_SOE_DisCharge_42 : 42|10@1+ (0.1,0) [0|102.3] "%"  PC,MBMU
 SG_ S2A_StepChrMode_42 : 52|1@1+ (1,0) [0|1] ""  PC,MBMU

BO_ 2333474667 S2A_SUMDATA15__43: 8 SBMU
 SG_ BAT_SysremainEngy_Charge_43 : 0|16@1+ (0.1,0) [0|6553.5] "kWh"  PC,MBMU
 SG_ BAT_SysremainEngy_DisCharge_43 : 16|16@1+ (0.1,0) [0|6553.5] "kWh"  PC,MBMU
 SG_ BAT_SOE_Charge_43 : 32|10@1+ (0.1,0) [0|102.3] "%"  PC,MBMU
 SG_ BAT_SOE_DisCharge_43 : 42|10@1+ (0.1,0) [0|102.3] "%"  PC,MBMU
 SG_ S2A_StepChrMode_43 : 52|1@1+ (1,0) [0|1] ""  PC,MBMU

BO_ 2333474668 S2A_SUMDATA15__44: 8 SBMU
 SG_ BAT_SysremainEngy_Charge_44 : 0|16@1+ (0.1,0) [0|6553.5] "kWh"  PC,MBMU
 SG_ BAT_SysremainEngy_DisCharge_44 : 16|16@1+ (0.1,0) [0|6553.5] "kWh"  PC,MBMU
 SG_ BAT_SOE_Charge_44 : 32|10@1+ (0.1,0) [0|102.3] "%"  PC,MBMU
 SG_ BAT_SOE_DisCharge_44 : 42|10@1+ (0.1,0) [0|102.3] "%"  PC,MBMU
 SG_ S2A_StepChrMode_44 : 52|1@1+ (1,0) [0|1] ""  PC,MBMU

BO_ 2333474669 S2A_SUMDATA15__45: 8 SBMU
 SG_ BAT_SysremainEngy_Charge_45 : 0|16@1+ (0.1,0) [0|6553.5] "kWh"  PC,MBMU
 SG_ BAT_SysremainEngy_DisCharge_45 : 16|16@1+ (0.1,0) [0|6553.5] "kWh"  PC,MBMU
 SG_ BAT_SOE_Charge_45 : 32|10@1+ (0.1,0) [0|102.3] "%"  PC,MBMU
 SG_ BAT_SOE_DisCharge_45 : 42|10@1+ (0.1,0) [0|102.3] "%"  PC,MBMU
 SG_ S2A_StepChrMode_45 : 52|1@1+ (1,0) [0|1] ""  PC,MBMU

BO_ 2333474670 S2A_SUMDATA15__46: 8 SBMU
 SG_ BAT_SysremainEngy_Charge_46 : 0|16@1+ (0.1,0) [0|6553.5] "kWh"  PC,MBMU
 SG_ BAT_SysremainEngy_DisCharge_46 : 16|16@1+ (0.1,0) [0|6553.5] "kWh"  PC,MBMU
 SG_ BAT_SOE_Charge_46 : 32|10@1+ (0.1,0) [0|102.3] "%"  PC,MBMU
 SG_ BAT_SOE_DisCharge_46 : 42|10@1+ (0.1,0) [0|102.3] "%"  PC,MBMU
 SG_ S2A_StepChrMode_46 : 52|1@1+ (1,0) [0|1] ""  PC,MBMU

BO_ 2333474671 S2A_SUMDATA15__47: 8 SBMU
 SG_ BAT_SysremainEngy_Charge_47 : 0|16@1+ (0.1,0) [0|6553.5] "kWh"  PC,MBMU
 SG_ BAT_SysremainEngy_DisCharge_47 : 16|16@1+ (0.1,0) [0|6553.5] "kWh"  PC,MBMU
 SG_ BAT_SOE_Charge_47 : 32|10@1+ (0.1,0) [0|102.3] "%"  PC,MBMU
 SG_ BAT_SOE_DisCharge_47 : 42|10@1+ (0.1,0) [0|102.3] "%"  PC,MBMU
 SG_ S2A_StepChrMode_47 : 52|1@1+ (1,0) [0|1] ""  PC,MBMU

BO_ 2333474672 S2A_SUMDATA15__48: 8 SBMU
 SG_ BAT_SysremainEngy_Charge_48 : 0|16@1+ (0.1,0) [0|6553.5] "kWh"  PC,MBMU
 SG_ BAT_SysremainEngy_DisCharge_48 : 16|16@1+ (0.1,0) [0|6553.5] "kWh"  PC,MBMU
 SG_ BAT_SOE_Charge_48 : 32|10@1+ (0.1,0) [0|102.3] "%"  PC,MBMU
 SG_ BAT_SOE_DisCharge_48 : 42|10@1+ (0.1,0) [0|102.3] "%"  PC,MBMU
 SG_ S2A_StepChrMode_48 : 52|1@1+ (1,0) [0|1] ""  PC,MBMU

BO_ 2333474673 S2A_SUMDATA15__49: 8 SBMU
 SG_ BAT_SysremainEngy_Charge_49 : 0|16@1+ (0.1,0) [0|6553.5] "kWh"  PC,MBMU
 SG_ BAT_SysremainEngy_DisCharge_49 : 16|16@1+ (0.1,0) [0|6553.5] "kWh"  PC,MBMU
 SG_ BAT_SOE_Charge_49 : 32|10@1+ (0.1,0) [0|102.3] "%"  PC,MBMU
 SG_ BAT_SOE_DisCharge_49 : 42|10@1+ (0.1,0) [0|102.3] "%"  PC,MBMU
 SG_ S2A_StepChrMode_49 : 52|1@1+ (1,0) [0|1] ""  PC,MBMU

BO_ 2333474674 S2A_SUMDATA15__50: 8 SBMU
 SG_ BAT_SysremainEngy_Charge_50 : 0|16@1+ (0.1,0) [0|6553.5] "kWh"  PC,MBMU
 SG_ BAT_SysremainEngy_DisCharge_50 : 16|16@1+ (0.1,0) [0|6553.5] "kWh"  PC,MBMU
 SG_ BAT_SOE_Charge_50 : 32|10@1+ (0.1,0) [0|102.3] "%"  PC,MBMU
 SG_ BAT_SOE_DisCharge_50 : 42|10@1+ (0.1,0) [0|102.3] "%"  PC,MBMU
 SG_ S2A_StepChrMode_50 : 52|1@1+ (1,0) [0|1] ""  PC,MBMU

BO_ 2333474675 S2A_SUMDATA15__51: 8 SBMU
 SG_ BAT_SysremainEngy_Charge_51 : 0|16@1+ (0.1,0) [0|6553.5] "kWh"  PC,MBMU
 SG_ BAT_SysremainEngy_DisCharge_51 : 16|16@1+ (0.1,0) [0|6553.5] "kWh"  PC,MBMU
 SG_ BAT_SOE_Charge_51 : 32|10@1+ (0.1,0) [0|102.3] "%"  PC,MBMU
 SG_ BAT_SOE_DisCharge_51 : 42|10@1+ (0.1,0) [0|102.3] "%"  PC,MBMU
 SG_ S2A_StepChrMode_51 : 52|1@1+ (1,0) [0|1] ""  PC,MBMU

BO_ 2333474676 S2A_SUMDATA15__52: 8 SBMU
 SG_ BAT_SysremainEngy_Charge_52 : 0|16@1+ (0.1,0) [0|6553.5] "kWh"  PC,MBMU
 SG_ BAT_SysremainEngy_DisCharge_52 : 16|16@1+ (0.1,0) [0|6553.5] "kWh"  PC,MBMU
 SG_ BAT_SOE_Charge_52 : 32|10@1+ (0.1,0) [0|102.3] "%"  PC,MBMU
 SG_ BAT_SOE_DisCharge_52 : 42|10@1+ (0.1,0) [0|102.3] "%"  PC,MBMU
 SG_ S2A_StepChrMode_52 : 52|1@1+ (1,0) [0|1] ""  PC,MBMU

BO_ 2333474677 S2A_SUMDATA15__53: 8 SBMU
 SG_ BAT_SysremainEngy_Charge_53 : 0|16@1+ (0.1,0) [0|6553.5] "kWh"  PC,MBMU
 SG_ BAT_SysremainEngy_DisCharge_53 : 16|16@1+ (0.1,0) [0|6553.5] "kWh"  PC,MBMU
 SG_ BAT_SOE_Charge_53 : 32|10@1+ (0.1,0) [0|102.3] "%"  PC,MBMU
 SG_ BAT_SOE_DisCharge_53 : 42|10@1+ (0.1,0) [0|102.3] "%"  PC,MBMU
 SG_ S2A_StepChrMode_53 : 52|1@1+ (1,0) [0|1] ""  PC,MBMU

BO_ 2333474678 S2A_SUMDATA15__54: 8 SBMU
 SG_ BAT_SysremainEngy_Charge_54 : 0|16@1+ (0.1,0) [0|6553.5] "kWh"  PC,MBMU
 SG_ BAT_SysremainEngy_DisCharge_54 : 16|16@1+ (0.1,0) [0|6553.5] "kWh"  PC,MBMU
 SG_ BAT_SOE_Charge_54 : 32|10@1+ (0.1,0) [0|102.3] "%"  PC,MBMU
 SG_ BAT_SOE_DisCharge_54 : 42|10@1+ (0.1,0) [0|102.3] "%"  PC,MBMU
 SG_ S2A_StepChrMode_54 : 52|1@1+ (1,0) [0|1] ""  PC,MBMU

BO_ 2333474679 S2A_SUMDATA15__55: 8 SBMU
 SG_ BAT_SysremainEngy_Charge_55 : 0|16@1+ (0.1,0) [0|6553.5] "kWh"  PC,MBMU
 SG_ BAT_SysremainEngy_DisCharge_55 : 16|16@1+ (0.1,0) [0|6553.5] "kWh"  PC,MBMU
 SG_ BAT_SOE_Charge_55 : 32|10@1+ (0.1,0) [0|102.3] "%"  PC,MBMU
 SG_ BAT_SOE_DisCharge_55 : 42|10@1+ (0.1,0) [0|102.3] "%"  PC,MBMU
 SG_ S2A_StepChrMode_55 : 52|1@1+ (1,0) [0|1] ""  PC,MBMU

BO_ 2333474680 S2A_SUMDATA15__56: 8 SBMU
 SG_ BAT_SysremainEngy_Charge_56 : 0|16@1+ (0.1,0) [0|6553.5] "kWh"  PC,MBMU
 SG_ BAT_SysremainEngy_DisCharge_56 : 16|16@1+ (0.1,0) [0|6553.5] "kWh"  PC,MBMU
 SG_ BAT_SOE_Charge_56 : 32|10@1+ (0.1,0) [0|102.3] "%"  PC,MBMU
 SG_ BAT_SOE_DisCharge_56 : 42|10@1+ (0.1,0) [0|102.3] "%"  PC,MBMU
 SG_ S2A_StepChrMode_56 : 52|1@1+ (1,0) [0|1] ""  PC,MBMU

BO_ 2333474681 S2A_SUMDATA15__57: 8 SBMU
 SG_ BAT_SysremainEngy_Charge_57 : 0|16@1+ (0.1,0) [0|6553.5] "kWh"  PC,MBMU
 SG_ BAT_SysremainEngy_DisCharge_57 : 16|16@1+ (0.1,0) [0|6553.5] "kWh"  PC,MBMU
 SG_ BAT_SOE_Charge_57 : 32|10@1+ (0.1,0) [0|102.3] "%"  PC,MBMU
 SG_ BAT_SOE_DisCharge_57 : 42|10@1+ (0.1,0) [0|102.3] "%"  PC,MBMU
 SG_ S2A_StepChrMode_57 : 52|1@1+ (1,0) [0|1] ""  PC,MBMU

BO_ 2333474682 S2A_SUMDATA15__58: 8 SBMU
 SG_ BAT_SysremainEngy_Charge_58 : 0|16@1+ (0.1,0) [0|6553.5] "kWh"  PC,MBMU
 SG_ BAT_SysremainEngy_DisCharge_58 : 16|16@1+ (0.1,0) [0|6553.5] "kWh"  PC,MBMU
 SG_ BAT_SOE_Charge_58 : 32|10@1+ (0.1,0) [0|102.3] "%"  PC,MBMU
 SG_ BAT_SOE_DisCharge_58 : 42|10@1+ (0.1,0) [0|102.3] "%"  PC,MBMU
 SG_ S2A_StepChrMode_58 : 52|1@1+ (1,0) [0|1] ""  PC,MBMU

BO_ 2333474683 S2A_SUMDATA15__59: 8 SBMU
 SG_ BAT_SysremainEngy_Charge_59 : 0|16@1+ (0.1,0) [0|6553.5] "kWh"  PC,MBMU
 SG_ BAT_SysremainEngy_DisCharge_59 : 16|16@1+ (0.1,0) [0|6553.5] "kWh"  PC,MBMU
 SG_ BAT_SOE_Charge_59 : 32|10@1+ (0.1,0) [0|102.3] "%"  PC,MBMU
 SG_ BAT_SOE_DisCharge_59 : 42|10@1+ (0.1,0) [0|102.3] "%"  PC,MBMU
 SG_ S2A_StepChrMode_59 : 52|1@1+ (1,0) [0|1] ""  PC,MBMU

BO_ 2333474684 S2A_SUMDATA15__60: 8 SBMU
 SG_ BAT_SysremainEngy_Charge_60 : 0|16@1+ (0.1,0) [0|6553.5] "kWh"  PC,MBMU
 SG_ BAT_SysremainEngy_DisCharge_60 : 16|16@1+ (0.1,0) [0|6553.5] "kWh"  PC,MBMU
 SG_ BAT_SOE_Charge_60 : 32|10@1+ (0.1,0) [0|102.3] "%"  PC,MBMU
 SG_ BAT_SOE_DisCharge_60 : 42|10@1+ (0.1,0) [0|102.3] "%"  PC,MBMU
 SG_ S2A_StepChrMode_60 : 52|1@1+ (1,0) [0|1] ""  PC,MBMU

BO_ 2333474685 S2A_SUMDATA15__61: 8 SBMU
 SG_ BAT_SysremainEngy_Charge_61 : 0|16@1+ (0.1,0) [0|6553.5] "kWh"  PC,MBMU
 SG_ BAT_SysremainEngy_DisCharge_61 : 16|16@1+ (0.1,0) [0|6553.5] "kWh"  PC,MBMU
 SG_ BAT_SOE_Charge_61 : 32|10@1+ (0.1,0) [0|102.3] "%"  PC,MBMU
 SG_ BAT_SOE_DisCharge_61 : 42|10@1+ (0.1,0) [0|102.3] "%"  PC,MBMU
 SG_ S2A_StepChrMode_61 : 52|1@1+ (1,0) [0|1] ""  PC,MBMU

BO_ 2333474686 S2A_SUMDATA15__62: 8 SBMU
 SG_ BAT_SysremainEngy_Charge_62 : 0|16@1+ (0.1,0) [0|6553.5] "kWh"  PC,MBMU
 SG_ BAT_SysremainEngy_DisCharge_62 : 16|16@1+ (0.1,0) [0|6553.5] "kWh"  PC,MBMU
 SG_ BAT_SOE_Charge_62 : 32|10@1+ (0.1,0) [0|102.3] "%"  PC,MBMU
 SG_ BAT_SOE_DisCharge_62 : 42|10@1+ (0.1,0) [0|102.3] "%"  PC,MBMU
 SG_ S2A_StepChrMode_62 : 52|1@1+ (1,0) [0|1] ""  PC,MBMU

BO_ 2333474687 S2A_SUMDATA15__63: 8 SBMU
 SG_ BAT_SysremainEngy_Charge_63 : 0|16@1+ (0.1,0) [0|6553.5] "kWh"  PC,MBMU
 SG_ BAT_SysremainEngy_DisCharge_63 : 16|16@1+ (0.1,0) [0|6553.5] "kWh"  PC,MBMU
 SG_ BAT_SOE_Charge_63 : 32|10@1+ (0.1,0) [0|102.3] "%"  PC,MBMU
 SG_ BAT_SOE_DisCharge_63 : 42|10@1+ (0.1,0) [0|102.3] "%"  PC,MBMU
 SG_ S2A_StepChrMode_63 : 52|1@1+ (1,0) [0|1] ""  PC,MBMU

BO_ 2333540161 S2A_SUMDATA16__01: 8 SBMU
 SG_ BAT_Lmt_ChCurrent_01 : 0|16@1+ (0.1,-2000) [-2000|4553.5] "A"  PC,MBMU
 SG_ BAT_Lmt_DisChCurrent_01 : 16|16@1+ (0.1,-2000) [-2000|4553.5] "A"  PC,MBMU
 SG_ BAT_Lmt_ChPwr_01 : 32|16@1+ (0.1,-2000) [-2000|4553.5] "Kw"  PC,MBMU
 SG_ BAT_Lmt_DisChPwr_01 : 48|16@1+ (0.1,-2000) [-2000|4553.5] "Kw"  PC,MBMU

BO_ 2333540162 S2A_SUMDATA16__02: 8 SBMU
 SG_ BAT_Lmt_ChCurrent_02 : 0|16@1+ (0.1,-2000) [-2000|4553.5] "A"  PC,MBMU
 SG_ BAT_Lmt_DisChCurrent_02 : 16|16@1+ (0.1,-2000) [-2000|4553.5] "A"  PC,MBMU
 SG_ BAT_Lmt_ChPwr_02 : 32|16@1+ (0.1,-2000) [-2000|4553.5] "Kw"  PC,MBMU
 SG_ BAT_Lmt_DisChPwr_02 : 48|16@1+ (0.1,-2000) [-2000|4553.5] "Kw"  PC,MBMU

BO_ 2333540163 S2A_SUMDATA16__03: 8 SBMU
 SG_ BAT_Lmt_ChCurrent_03 : 0|16@1+ (0.1,-2000) [-2000|4553.5] "A"  PC,MBMU
 SG_ BAT_Lmt_DisChCurrent_03 : 16|16@1+ (0.1,-2000) [-2000|4553.5] "A"  PC,MBMU
 SG_ BAT_Lmt_ChPwr_03 : 32|16@1+ (0.1,-2000) [-2000|4553.5] "Kw"  PC,MBMU
 SG_ BAT_Lmt_DisChPwr_03 : 48|16@1+ (0.1,-2000) [-2000|4553.5] "Kw"  PC,MBMU

BO_ 2333540164 S2A_SUMDATA16__04: 8 SBMU
 SG_ BAT_Lmt_ChCurrent_04 : 0|16@1+ (0.1,-2000) [-2000|4553.5] "A"  PC,MBMU
 SG_ BAT_Lmt_DisChCurrent_04 : 16|16@1+ (0.1,-2000) [-2000|4553.5] "A"  PC,MBMU
 SG_ BAT_Lmt_ChPwr_04 : 32|16@1+ (0.1,-2000) [-2000|4553.5] "Kw"  PC,MBMU
 SG_ BAT_Lmt_DisChPwr_04 : 48|16@1+ (0.1,-2000) [-2000|4553.5] "Kw"  PC,MBMU

BO_ 2333540165 S2A_SUMDATA16__05: 8 SBMU
 SG_ BAT_Lmt_ChCurrent_05 : 0|16@1+ (0.1,-2000) [-2000|4553.5] "A"  PC,MBMU
 SG_ BAT_Lmt_DisChCurrent_05 : 16|16@1+ (0.1,-2000) [-2000|4553.5] "A"  PC,MBMU
 SG_ BAT_Lmt_ChPwr_05 : 32|16@1+ (0.1,-2000) [-2000|4553.5] "Kw"  PC,MBMU
 SG_ BAT_Lmt_DisChPwr_05 : 48|16@1+ (0.1,-2000) [-2000|4553.5] "Kw"  PC,MBMU

BO_ 2333540166 S2A_SUMDATA16__06: 8 SBMU
 SG_ BAT_Lmt_ChCurrent_06 : 0|16@1+ (0.1,-2000) [-2000|4553.5] "A"  PC,MBMU
 SG_ BAT_Lmt_DisChCurrent_06 : 16|16@1+ (0.1,-2000) [-2000|4553.5] "A"  PC,MBMU
 SG_ BAT_Lmt_ChPwr_06 : 32|16@1+ (0.1,-2000) [-2000|4553.5] "Kw"  PC,MBMU
 SG_ BAT_Lmt_DisChPwr_06 : 48|16@1+ (0.1,-2000) [-2000|4553.5] "Kw"  PC,MBMU

BO_ 2333540167 S2A_SUMDATA16__07: 8 SBMU
 SG_ BAT_Lmt_ChCurrent_07 : 0|16@1+ (0.1,-2000) [-2000|4553.5] "A"  PC,MBMU
 SG_ BAT_Lmt_DisChCurrent_07 : 16|16@1+ (0.1,-2000) [-2000|4553.5] "A"  PC,MBMU
 SG_ BAT_Lmt_ChPwr_07 : 32|16@1+ (0.1,-2000) [-2000|4553.5] "Kw"  PC,MBMU
 SG_ BAT_Lmt_DisChPwr_07 : 48|16@1+ (0.1,-2000) [-2000|4553.5] "Kw"  PC,MBMU

BO_ 2333540168 S2A_SUMDATA16__08: 8 SBMU
 SG_ BAT_Lmt_ChCurrent_08 : 0|16@1+ (0.1,-2000) [-2000|4553.5] "A"  PC,MBMU
 SG_ BAT_Lmt_DisChCurrent_08 : 16|16@1+ (0.1,-2000) [-2000|4553.5] "A"  PC,MBMU
 SG_ BAT_Lmt_ChPwr_08 : 32|16@1+ (0.1,-2000) [-2000|4553.5] "Kw"  PC,MBMU
 SG_ BAT_Lmt_DisChPwr_08 : 48|16@1+ (0.1,-2000) [-2000|4553.5] "Kw"  PC,MBMU

BO_ 2333540169 S2A_SUMDATA16__09: 8 SBMU
 SG_ BAT_Lmt_ChCurrent_09 : 0|16@1+ (0.1,-2000) [-2000|4553.5] "A"  PC,MBMU
 SG_ BAT_Lmt_DisChCurrent_09 : 16|16@1+ (0.1,-2000) [-2000|4553.5] "A"  PC,MBMU
 SG_ BAT_Lmt_ChPwr_09 : 32|16@1+ (0.1,-2000) [-2000|4553.5] "Kw"  PC,MBMU
 SG_ BAT_Lmt_DisChPwr_09 : 48|16@1+ (0.1,-2000) [-2000|4553.5] "Kw"  PC,MBMU

BO_ 2333540170 S2A_SUMDATA16__10: 8 SBMU
 SG_ BAT_Lmt_ChCurrent_10 : 0|16@1+ (0.1,-2000) [-2000|4553.5] "A"  PC,MBMU
 SG_ BAT_Lmt_DisChCurrent_10 : 16|16@1+ (0.1,-2000) [-2000|4553.5] "A"  PC,MBMU
 SG_ BAT_Lmt_ChPwr_10 : 32|16@1+ (0.1,-2000) [-2000|4553.5] "Kw"  PC,MBMU
 SG_ BAT_Lmt_DisChPwr_10 : 48|16@1+ (0.1,-2000) [-2000|4553.5] "Kw"  PC,MBMU

BO_ 2333540171 S2A_SUMDATA16__11: 8 SBMU
 SG_ BAT_Lmt_ChCurrent_11 : 0|16@1+ (0.1,-2000) [-2000|4553.5] "A"  PC,MBMU
 SG_ BAT_Lmt_DisChCurrent_11 : 16|16@1+ (0.1,-2000) [-2000|4553.5] "A"  PC,MBMU
 SG_ BAT_Lmt_ChPwr_11 : 32|16@1+ (0.1,-2000) [-2000|4553.5] "Kw"  PC,MBMU
 SG_ BAT_Lmt_DisChPwr_11 : 48|16@1+ (0.1,-2000) [-2000|4553.5] "Kw"  PC,MBMU

BO_ 2333540172 S2A_SUMDATA16__12: 8 SBMU
 SG_ BAT_Lmt_ChCurrent_12 : 0|16@1+ (0.1,-2000) [-2000|4553.5] "A"  PC,MBMU
 SG_ BAT_Lmt_DisChCurrent_12 : 16|16@1+ (0.1,-2000) [-2000|4553.5] "A"  PC,MBMU
 SG_ BAT_Lmt_ChPwr_12 : 32|16@1+ (0.1,-2000) [-2000|4553.5] "Kw"  PC,MBMU
 SG_ BAT_Lmt_DisChPwr_12 : 48|16@1+ (0.1,-2000) [-2000|4553.5] "Kw"  PC,MBMU

BO_ 2333540173 S2A_SUMDATA16__13: 8 SBMU
 SG_ BAT_Lmt_ChCurrent_13 : 0|16@1+ (0.1,-2000) [-2000|4553.5] "A"  PC,MBMU
 SG_ BAT_Lmt_DisChCurrent_13 : 16|16@1+ (0.1,-2000) [-2000|4553.5] "A"  PC,MBMU
 SG_ BAT_Lmt_ChPwr_13 : 32|16@1+ (0.1,-2000) [-2000|4553.5] "Kw"  PC,MBMU
 SG_ BAT_Lmt_DisChPwr_13 : 48|16@1+ (0.1,-2000) [-2000|4553.5] "Kw"  PC,MBMU

BO_ 2333540174 S2A_SUMDATA16__14: 8 SBMU
 SG_ BAT_Lmt_ChCurrent_14 : 0|16@1+ (0.1,-2000) [-2000|4553.5] "A"  PC,MBMU
 SG_ BAT_Lmt_DisChCurrent_14 : 16|16@1+ (0.1,-2000) [-2000|4553.5] "A"  PC,MBMU
 SG_ BAT_Lmt_ChPwr_14 : 32|16@1+ (0.1,-2000) [-2000|4553.5] "Kw"  PC,MBMU
 SG_ BAT_Lmt_DisChPwr_14 : 48|16@1+ (0.1,-2000) [-2000|4553.5] "Kw"  PC,MBMU

BO_ 2333540175 S2A_SUMDATA16__15: 8 SBMU
 SG_ BAT_Lmt_ChCurrent_15 : 0|16@1+ (0.1,-2000) [-2000|4553.5] "A"  PC,MBMU
 SG_ BAT_Lmt_DisChCurrent_15 : 16|16@1+ (0.1,-2000) [-2000|4553.5] "A"  PC,MBMU
 SG_ BAT_Lmt_ChPwr_15 : 32|16@1+ (0.1,-2000) [-2000|4553.5] "Kw"  PC,MBMU
 SG_ BAT_Lmt_DisChPwr_15 : 48|16@1+ (0.1,-2000) [-2000|4553.5] "Kw"  PC,MBMU

BO_ 2333540176 S2A_SUMDATA16__16: 8 SBMU
 SG_ BAT_Lmt_ChCurrent_16 : 0|16@1+ (0.1,-2000) [-2000|4553.5] "A"  PC,MBMU
 SG_ BAT_Lmt_DisChCurrent_16 : 16|16@1+ (0.1,-2000) [-2000|4553.5] "A"  PC,MBMU
 SG_ BAT_Lmt_ChPwr_16 : 32|16@1+ (0.1,-2000) [-2000|4553.5] "Kw"  PC,MBMU
 SG_ BAT_Lmt_DisChPwr_16 : 48|16@1+ (0.1,-2000) [-2000|4553.5] "Kw"  PC,MBMU

BO_ 2333540177 S2A_SUMDATA16__17: 8 SBMU
 SG_ BAT_Lmt_ChCurrent_17 : 0|16@1+ (0.1,-2000) [-2000|4553.5] "A"  PC,MBMU
 SG_ BAT_Lmt_DisChCurrent_17 : 16|16@1+ (0.1,-2000) [-2000|4553.5] "A"  PC,MBMU
 SG_ BAT_Lmt_ChPwr_17 : 32|16@1+ (0.1,-2000) [-2000|4553.5] "Kw"  PC,MBMU
 SG_ BAT_Lmt_DisChPwr_17 : 48|16@1+ (0.1,-2000) [-2000|4553.5] "Kw"  PC,MBMU

BO_ 2333540178 S2A_SUMDATA16__18: 8 SBMU
 SG_ BAT_Lmt_ChCurrent_18 : 0|16@1+ (0.1,-2000) [-2000|4553.5] "A"  PC,MBMU
 SG_ BAT_Lmt_DisChCurrent_18 : 16|16@1+ (0.1,-2000) [-2000|4553.5] "A"  PC,MBMU
 SG_ BAT_Lmt_ChPwr_18 : 32|16@1+ (0.1,-2000) [-2000|4553.5] "Kw"  PC,MBMU
 SG_ BAT_Lmt_DisChPwr_18 : 48|16@1+ (0.1,-2000) [-2000|4553.5] "Kw"  PC,MBMU

BO_ 2333540179 S2A_SUMDATA16__19: 8 SBMU
 SG_ BAT_Lmt_ChCurrent_19 : 0|16@1+ (0.1,-2000) [-2000|4553.5] "A"  PC,MBMU
 SG_ BAT_Lmt_DisChCurrent_19 : 16|16@1+ (0.1,-2000) [-2000|4553.5] "A"  PC,MBMU
 SG_ BAT_Lmt_ChPwr_19 : 32|16@1+ (0.1,-2000) [-2000|4553.5] "Kw"  PC,MBMU
 SG_ BAT_Lmt_DisChPwr_19 : 48|16@1+ (0.1,-2000) [-2000|4553.5] "Kw"  PC,MBMU

BO_ 2333540180 S2A_SUMDATA16__20: 8 SBMU
 SG_ BAT_Lmt_ChCurrent_20 : 0|16@1+ (0.1,-2000) [-2000|4553.5] "A"  PC,MBMU
 SG_ BAT_Lmt_DisChCurrent_20 : 16|16@1+ (0.1,-2000) [-2000|4553.5] "A"  PC,MBMU
 SG_ BAT_Lmt_ChPwr_20 : 32|16@1+ (0.1,-2000) [-2000|4553.5] "Kw"  PC,MBMU
 SG_ BAT_Lmt_DisChPwr_20 : 48|16@1+ (0.1,-2000) [-2000|4553.5] "Kw"  PC,MBMU

BO_ 2333540181 S2A_SUMDATA16__21: 8 SBMU
 SG_ BAT_Lmt_ChCurrent_21 : 0|16@1+ (0.1,-2000) [-2000|4553.5] "A"  PC,MBMU
 SG_ BAT_Lmt_DisChCurrent_21 : 16|16@1+ (0.1,-2000) [-2000|4553.5] "A"  PC,MBMU
 SG_ BAT_Lmt_ChPwr_21 : 32|16@1+ (0.1,-2000) [-2000|4553.5] "Kw"  PC,MBMU
 SG_ BAT_Lmt_DisChPwr_21 : 48|16@1+ (0.1,-2000) [-2000|4553.5] "Kw"  PC,MBMU

BO_ 2333540182 S2A_SUMDATA16__22: 8 SBMU
 SG_ BAT_Lmt_ChCurrent_22 : 0|16@1+ (0.1,-2000) [-2000|4553.5] "A"  PC,MBMU
 SG_ BAT_Lmt_DisChCurrent_22 : 16|16@1+ (0.1,-2000) [-2000|4553.5] "A"  PC,MBMU
 SG_ BAT_Lmt_ChPwr_22 : 32|16@1+ (0.1,-2000) [-2000|4553.5] "Kw"  PC,MBMU
 SG_ BAT_Lmt_DisChPwr_22 : 48|16@1+ (0.1,-2000) [-2000|4553.5] "Kw"  PC,MBMU

BO_ 2333540183 S2A_SUMDATA16__23: 8 SBMU
 SG_ BAT_Lmt_ChCurrent_23 : 0|16@1+ (0.1,-2000) [-2000|4553.5] "A"  PC,MBMU
 SG_ BAT_Lmt_DisChCurrent_23 : 16|16@1+ (0.1,-2000) [-2000|4553.5] "A"  PC,MBMU
 SG_ BAT_Lmt_ChPwr_23 : 32|16@1+ (0.1,-2000) [-2000|4553.5] "Kw"  PC,MBMU
 SG_ BAT_Lmt_DisChPwr_23 : 48|16@1+ (0.1,-2000) [-2000|4553.5] "Kw"  PC,MBMU

BO_ 2333540184 S2A_SUMDATA16__24: 8 SBMU
 SG_ BAT_Lmt_ChCurrent_24 : 0|16@1+ (0.1,-2000) [-2000|4553.5] "A"  PC,MBMU
 SG_ BAT_Lmt_DisChCurrent_24 : 16|16@1+ (0.1,-2000) [-2000|4553.5] "A"  PC,MBMU
 SG_ BAT_Lmt_ChPwr_24 : 32|16@1+ (0.1,-2000) [-2000|4553.5] "Kw"  PC,MBMU
 SG_ BAT_Lmt_DisChPwr_24 : 48|16@1+ (0.1,-2000) [-2000|4553.5] "Kw"  PC,MBMU

BO_ 2333540185 S2A_SUMDATA16__25: 8 SBMU
 SG_ BAT_Lmt_ChCurrent_25 : 0|16@1+ (0.1,-2000) [-2000|4553.5] "A"  PC,MBMU
 SG_ BAT_Lmt_DisChCurrent_25 : 16|16@1+ (0.1,-2000) [-2000|4553.5] "A"  PC,MBMU
 SG_ BAT_Lmt_ChPwr_25 : 32|16@1+ (0.1,-2000) [-2000|4553.5] "Kw"  PC,MBMU
 SG_ BAT_Lmt_DisChPwr_25 : 48|16@1+ (0.1,-2000) [-2000|4553.5] "Kw"  PC,MBMU

BO_ 2333540186 S2A_SUMDATA16__26: 8 SBMU
 SG_ BAT_Lmt_ChCurrent_26 : 0|16@1+ (0.1,-2000) [-2000|4553.5] "A"  PC,MBMU
 SG_ BAT_Lmt_DisChCurrent_26 : 16|16@1+ (0.1,-2000) [-2000|4553.5] "A"  PC,MBMU
 SG_ BAT_Lmt_ChPwr_26 : 32|16@1+ (0.1,-2000) [-2000|4553.5] "Kw"  PC,MBMU
 SG_ BAT_Lmt_DisChPwr_26 : 48|16@1+ (0.1,-2000) [-2000|4553.5] "Kw"  PC,MBMU

BO_ 2333540187 S2A_SUMDATA16__27: 8 SBMU
 SG_ BAT_Lmt_ChCurrent_27 : 0|16@1+ (0.1,-2000) [-2000|4553.5] "A"  PC,MBMU
 SG_ BAT_Lmt_DisChCurrent_27 : 16|16@1+ (0.1,-2000) [-2000|4553.5] "A"  PC,MBMU
 SG_ BAT_Lmt_ChPwr_27 : 32|16@1+ (0.1,-2000) [-2000|4553.5] "Kw"  PC,MBMU
 SG_ BAT_Lmt_DisChPwr_27 : 48|16@1+ (0.1,-2000) [-2000|4553.5] "Kw"  PC,MBMU

BO_ 2333540188 S2A_SUMDATA16__28: 8 SBMU
 SG_ BAT_Lmt_ChCurrent_28 : 0|16@1+ (0.1,-2000) [-2000|4553.5] "A"  PC,MBMU
 SG_ BAT_Lmt_DisChCurrent_28 : 16|16@1+ (0.1,-2000) [-2000|4553.5] "A"  PC,MBMU
 SG_ BAT_Lmt_ChPwr_28 : 32|16@1+ (0.1,-2000) [-2000|4553.5] "Kw"  PC,MBMU
 SG_ BAT_Lmt_DisChPwr_28 : 48|16@1+ (0.1,-2000) [-2000|4553.5] "Kw"  PC,MBMU

BO_ 2333540189 S2A_SUMDATA16__29: 8 SBMU
 SG_ BAT_Lmt_ChCurrent_29 : 0|16@1+ (0.1,-2000) [-2000|4553.5] "A"  PC,MBMU
 SG_ BAT_Lmt_DisChCurrent_29 : 16|16@1+ (0.1,-2000) [-2000|4553.5] "A"  PC,MBMU
 SG_ BAT_Lmt_ChPwr_29 : 32|16@1+ (0.1,-2000) [-2000|4553.5] "Kw"  PC,MBMU
 SG_ BAT_Lmt_DisChPwr_29 : 48|16@1+ (0.1,-2000) [-2000|4553.5] "Kw"  PC,MBMU

BO_ 2333540190 S2A_SUMDATA16__30: 8 SBMU
 SG_ BAT_Lmt_ChCurrent_30 : 0|16@1+ (0.1,-2000) [-2000|4553.5] "A"  PC,MBMU
 SG_ BAT_Lmt_DisChCurrent_30 : 16|16@1+ (0.1,-2000) [-2000|4553.5] "A"  PC,MBMU
 SG_ BAT_Lmt_ChPwr_30 : 32|16@1+ (0.1,-2000) [-2000|4553.5] "Kw"  PC,MBMU
 SG_ BAT_Lmt_DisChPwr_30 : 48|16@1+ (0.1,-2000) [-2000|4553.5] "Kw"  PC,MBMU

BO_ 2333540191 S2A_SUMDATA16__31: 8 SBMU
 SG_ BAT_Lmt_ChCurrent_31 : 0|16@1+ (0.1,-2000) [-2000|4553.5] "A"  PC,MBMU
 SG_ BAT_Lmt_DisChCurrent_31 : 16|16@1+ (0.1,-2000) [-2000|4553.5] "A"  PC,MBMU
 SG_ BAT_Lmt_ChPwr_31 : 32|16@1+ (0.1,-2000) [-2000|4553.5] "Kw"  PC,MBMU
 SG_ BAT_Lmt_DisChPwr_31 : 48|16@1+ (0.1,-2000) [-2000|4553.5] "Kw"  PC,MBMU

BO_ 2333540192 S2A_SUMDATA16__32: 8 SBMU
 SG_ BAT_Lmt_ChCurrent_32 : 0|16@1+ (0.1,-2000) [-2000|4553.5] "A"  PC,MBMU
 SG_ BAT_Lmt_DisChCurrent_32 : 16|16@1+ (0.1,-2000) [-2000|4553.5] "A"  PC,MBMU
 SG_ BAT_Lmt_ChPwr_32 : 32|16@1+ (0.1,-2000) [-2000|4553.5] "Kw"  PC,MBMU
 SG_ BAT_Lmt_DisChPwr_32 : 48|16@1+ (0.1,-2000) [-2000|4553.5] "Kw"  PC,MBMU

BO_ 2333540193 S2A_SUMDATA16__33: 8 SBMU
 SG_ BAT_Lmt_ChCurrent_33 : 0|16@1+ (0.1,-2000) [-2000|4553.5] "A"  PC,MBMU
 SG_ BAT_Lmt_DisChCurrent_33 : 16|16@1+ (0.1,-2000) [-2000|4553.5] "A"  PC,MBMU
 SG_ BAT_Lmt_ChPwr_33 : 32|16@1+ (0.1,-2000) [-2000|4553.5] "Kw"  PC,MBMU
 SG_ BAT_Lmt_DisChPwr_33 : 48|16@1+ (0.1,-2000) [-2000|4553.5] "Kw"  PC,MBMU

BO_ 2333540194 S2A_SUMDATA16__34: 8 SBMU
 SG_ BAT_Lmt_ChCurrent_34 : 0|16@1+ (0.1,-2000) [-2000|4553.5] "A"  PC,MBMU
 SG_ BAT_Lmt_DisChCurrent_34 : 16|16@1+ (0.1,-2000) [-2000|4553.5] "A"  PC,MBMU
 SG_ BAT_Lmt_ChPwr_34 : 32|16@1+ (0.1,-2000) [-2000|4553.5] "Kw"  PC,MBMU
 SG_ BAT_Lmt_DisChPwr_34 : 48|16@1+ (0.1,-2000) [-2000|4553.5] "Kw"  PC,MBMU

BO_ 2333540195 S2A_SUMDATA16__35: 8 SBMU
 SG_ BAT_Lmt_ChCurrent_35 : 0|16@1+ (0.1,-2000) [-2000|4553.5] "A"  PC,MBMU
 SG_ BAT_Lmt_DisChCurrent_35 : 16|16@1+ (0.1,-2000) [-2000|4553.5] "A"  PC,MBMU
 SG_ BAT_Lmt_ChPwr_35 : 32|16@1+ (0.1,-2000) [-2000|4553.5] "Kw"  PC,MBMU
 SG_ BAT_Lmt_DisChPwr_35 : 48|16@1+ (0.1,-2000) [-2000|4553.5] "Kw"  PC,MBMU

BO_ 2333540196 S2A_SUMDATA16__36: 8 SBMU
 SG_ BAT_Lmt_ChCurrent_36 : 0|16@1+ (0.1,-2000) [-2000|4553.5] "A"  PC,MBMU
 SG_ BAT_Lmt_DisChCurrent_36 : 16|16@1+ (0.1,-2000) [-2000|4553.5] "A"  PC,MBMU
 SG_ BAT_Lmt_ChPwr_36 : 32|16@1+ (0.1,-2000) [-2000|4553.5] "Kw"  PC,MBMU
 SG_ BAT_Lmt_DisChPwr_36 : 48|16@1+ (0.1,-2000) [-2000|4553.5] "Kw"  PC,MBMU

BO_ 2333540197 S2A_SUMDATA16__37: 8 SBMU
 SG_ BAT_Lmt_ChCurrent_37 : 0|16@1+ (0.1,-2000) [-2000|4553.5] "A"  PC,MBMU
 SG_ BAT_Lmt_DisChCurrent_37 : 16|16@1+ (0.1,-2000) [-2000|4553.5] "A"  PC,MBMU
 SG_ BAT_Lmt_ChPwr_37 : 32|16@1+ (0.1,-2000) [-2000|4553.5] "Kw"  PC,MBMU
 SG_ BAT_Lmt_DisChPwr_37 : 48|16@1+ (0.1,-2000) [-2000|4553.5] "Kw"  PC,MBMU

BO_ 2333540198 S2A_SUMDATA16__38: 8 SBMU
 SG_ BAT_Lmt_ChCurrent_38 : 0|16@1+ (0.1,-2000) [-2000|4553.5] "A"  PC,MBMU
 SG_ BAT_Lmt_DisChCurrent_38 : 16|16@1+ (0.1,-2000) [-2000|4553.5] "A"  PC,MBMU
 SG_ BAT_Lmt_ChPwr_38 : 32|16@1+ (0.1,-2000) [-2000|4553.5] "Kw"  PC,MBMU
 SG_ BAT_Lmt_DisChPwr_38 : 48|16@1+ (0.1,-2000) [-2000|4553.5] "Kw"  PC,MBMU

BO_ 2333540199 S2A_SUMDATA16__39: 8 SBMU
 SG_ BAT_Lmt_ChCurrent_39 : 0|16@1+ (0.1,-2000) [-2000|4553.5] "A"  PC,MBMU
 SG_ BAT_Lmt_DisChCurrent_39 : 16|16@1+ (0.1,-2000) [-2000|4553.5] "A"  PC,MBMU
 SG_ BAT_Lmt_ChPwr_39 : 32|16@1+ (0.1,-2000) [-2000|4553.5] "Kw"  PC,MBMU
 SG_ BAT_Lmt_DisChPwr_39 : 48|16@1+ (0.1,-2000) [-2000|4553.5] "Kw"  PC,MBMU

BO_ 2333540200 S2A_SUMDATA16__40: 8 SBMU
 SG_ BAT_Lmt_ChCurrent_40 : 0|16@1+ (0.1,-2000) [-2000|4553.5] "A"  PC,MBMU
 SG_ BAT_Lmt_DisChCurrent_40 : 16|16@1+ (0.1,-2000) [-2000|4553.5] "A"  PC,MBMU
 SG_ BAT_Lmt_ChPwr_40 : 32|16@1+ (0.1,-2000) [-2000|4553.5] "Kw"  PC,MBMU
 SG_ BAT_Lmt_DisChPwr_40 : 48|16@1+ (0.1,-2000) [-2000|4553.5] "Kw"  PC,MBMU

BO_ 2333540201 S2A_SUMDATA16__41: 8 SBMU
 SG_ BAT_Lmt_ChCurrent_41 : 0|16@1+ (0.1,-2000) [-2000|4553.5] "A"  PC,MBMU
 SG_ BAT_Lmt_DisChCurrent_41 : 16|16@1+ (0.1,-2000) [-2000|4553.5] "A"  PC,MBMU
 SG_ BAT_Lmt_ChPwr_41 : 32|16@1+ (0.1,-2000) [-2000|4553.5] "Kw"  PC,MBMU
 SG_ BAT_Lmt_DisChPwr_41 : 48|16@1+ (0.1,-2000) [-2000|4553.5] "Kw"  PC,MBMU

BO_ 2333540202 S2A_SUMDATA16__42: 8 SBMU
 SG_ BAT_Lmt_ChCurrent_42 : 0|16@1+ (0.1,-2000) [-2000|4553.5] "A"  PC,MBMU
 SG_ BAT_Lmt_DisChCurrent_42 : 16|16@1+ (0.1,-2000) [-2000|4553.5] "A"  PC,MBMU
 SG_ BAT_Lmt_ChPwr_42 : 32|16@1+ (0.1,-2000) [-2000|4553.5] "Kw"  PC,MBMU
 SG_ BAT_Lmt_DisChPwr_42 : 48|16@1+ (0.1,-2000) [-2000|4553.5] "Kw"  PC,MBMU

BO_ 2333540203 S2A_SUMDATA16__43: 8 SBMU
 SG_ BAT_Lmt_ChCurrent_43 : 0|16@1+ (0.1,-2000) [-2000|4553.5] "A"  PC,MBMU
 SG_ BAT_Lmt_DisChCurrent_43 : 16|16@1+ (0.1,-2000) [-2000|4553.5] "A"  PC,MBMU
 SG_ BAT_Lmt_ChPwr_43 : 32|16@1+ (0.1,-2000) [-2000|4553.5] "Kw"  PC,MBMU
 SG_ BAT_Lmt_DisChPwr_43 : 48|16@1+ (0.1,-2000) [-2000|4553.5] "Kw"  PC,MBMU

BO_ 2333540204 S2A_SUMDATA16__44: 8 SBMU
 SG_ BAT_Lmt_ChCurrent_44 : 0|16@1+ (0.1,-2000) [-2000|4553.5] "A"  PC,MBMU
 SG_ BAT_Lmt_DisChCurrent_44 : 16|16@1+ (0.1,-2000) [-2000|4553.5] "A"  PC,MBMU
 SG_ BAT_Lmt_ChPwr_44 : 32|16@1+ (0.1,-2000) [-2000|4553.5] "Kw"  PC,MBMU
 SG_ BAT_Lmt_DisChPwr_44 : 48|16@1+ (0.1,-2000) [-2000|4553.5] "Kw"  PC,MBMU

BO_ 2333540205 S2A_SUMDATA16__45: 8 SBMU
 SG_ BAT_Lmt_ChCurrent_45 : 0|16@1+ (0.1,-2000) [-2000|4553.5] "A"  PC,MBMU
 SG_ BAT_Lmt_DisChCurrent_45 : 16|16@1+ (0.1,-2000) [-2000|4553.5] "A"  PC,MBMU
 SG_ BAT_Lmt_ChPwr_45 : 32|16@1+ (0.1,-2000) [-2000|4553.5] "Kw"  PC,MBMU
 SG_ BAT_Lmt_DisChPwr_45 : 48|16@1+ (0.1,-2000) [-2000|4553.5] "Kw"  PC,MBMU

BO_ 2333540206 S2A_SUMDATA16__46: 8 SBMU
 SG_ BAT_Lmt_ChCurrent_46 : 0|16@1+ (0.1,-2000) [-2000|4553.5] "A"  PC,MBMU
 SG_ BAT_Lmt_DisChCurrent_46 : 16|16@1+ (0.1,-2000) [-2000|4553.5] "A"  PC,MBMU
 SG_ BAT_Lmt_ChPwr_46 : 32|16@1+ (0.1,-2000) [-2000|4553.5] "Kw"  PC,MBMU
 SG_ BAT_Lmt_DisChPwr_46 : 48|16@1+ (0.1,-2000) [-2000|4553.5] "Kw"  PC,MBMU

BO_ 2333540207 S2A_SUMDATA16__47: 8 SBMU
 SG_ BAT_Lmt_ChCurrent_47 : 0|16@1+ (0.1,-2000) [-2000|4553.5] "A"  PC,MBMU
 SG_ BAT_Lmt_DisChCurrent_47 : 16|16@1+ (0.1,-2000) [-2000|4553.5] "A"  PC,MBMU
 SG_ BAT_Lmt_ChPwr_47 : 32|16@1+ (0.1,-2000) [-2000|4553.5] "Kw"  PC,MBMU
 SG_ BAT_Lmt_DisChPwr_47 : 48|16@1+ (0.1,-2000) [-2000|4553.5] "Kw"  PC,MBMU

BO_ 2333540208 S2A_SUMDATA16__48: 8 SBMU
 SG_ BAT_Lmt_ChCurrent_48 : 0|16@1+ (0.1,-2000) [-2000|4553.5] "A"  PC,MBMU
 SG_ BAT_Lmt_DisChCurrent_48 : 16|16@1+ (0.1,-2000) [-2000|4553.5] "A"  PC,MBMU
 SG_ BAT_Lmt_ChPwr_48 : 32|16@1+ (0.1,-2000) [-2000|4553.5] "Kw"  PC,MBMU
 SG_ BAT_Lmt_DisChPwr_48 : 48|16@1+ (0.1,-2000) [-2000|4553.5] "Kw"  PC,MBMU

BO_ 2333540209 S2A_SUMDATA16__49: 8 SBMU
 SG_ BAT_Lmt_ChCurrent_49 : 0|16@1+ (0.1,-2000) [-2000|4553.5] "A"  PC,MBMU
 SG_ BAT_Lmt_DisChCurrent_49 : 16|16@1+ (0.1,-2000) [-2000|4553.5] "A"  PC,MBMU
 SG_ BAT_Lmt_ChPwr_49 : 32|16@1+ (0.1,-2000) [-2000|4553.5] "Kw"  PC,MBMU
 SG_ BAT_Lmt_DisChPwr_49 : 48|16@1+ (0.1,-2000) [-2000|4553.5] "Kw"  PC,MBMU

BO_ 2333540210 S2A_SUMDATA16__50: 8 SBMU
 SG_ BAT_Lmt_ChCurrent_50 : 0|16@1+ (0.1,-2000) [-2000|4553.5] "A"  PC,MBMU
 SG_ BAT_Lmt_DisChCurrent_50 : 16|16@1+ (0.1,-2000) [-2000|4553.5] "A"  PC,MBMU
 SG_ BAT_Lmt_ChPwr_50 : 32|16@1+ (0.1,-2000) [-2000|4553.5] "Kw"  PC,MBMU
 SG_ BAT_Lmt_DisChPwr_50 : 48|16@1+ (0.1,-2000) [-2000|4553.5] "Kw"  PC,MBMU

BO_ 2333540211 S2A_SUMDATA16__51: 8 SBMU
 SG_ BAT_Lmt_ChCurrent_51 : 0|16@1+ (0.1,-2000) [-2000|4553.5] "A"  PC,MBMU
 SG_ BAT_Lmt_DisChCurrent_51 : 16|16@1+ (0.1,-2000) [-2000|4553.5] "A"  PC,MBMU
 SG_ BAT_Lmt_ChPwr_51 : 32|16@1+ (0.1,-2000) [-2000|4553.5] "Kw"  PC,MBMU
 SG_ BAT_Lmt_DisChPwr_51 : 48|16@1+ (0.1,-2000) [-2000|4553.5] "Kw"  PC,MBMU

BO_ 2333540212 S2A_SUMDATA16__52: 8 SBMU
 SG_ BAT_Lmt_ChCurrent_52 : 0|16@1+ (0.1,-2000) [-2000|4553.5] "A"  PC,MBMU
 SG_ BAT_Lmt_DisChCurrent_52 : 16|16@1+ (0.1,-2000) [-2000|4553.5] "A"  PC,MBMU
 SG_ BAT_Lmt_ChPwr_52 : 32|16@1+ (0.1,-2000) [-2000|4553.5] "Kw"  PC,MBMU
 SG_ BAT_Lmt_DisChPwr_52 : 48|16@1+ (0.1,-2000) [-2000|4553.5] "Kw"  PC,MBMU

BO_ 2333540213 S2A_SUMDATA16__53: 8 SBMU
 SG_ BAT_Lmt_ChCurrent_53 : 0|16@1+ (0.1,-2000) [-2000|4553.5] "A"  PC,MBMU
 SG_ BAT_Lmt_DisChCurrent_53 : 16|16@1+ (0.1,-2000) [-2000|4553.5] "A"  PC,MBMU
 SG_ BAT_Lmt_ChPwr_53 : 32|16@1+ (0.1,-2000) [-2000|4553.5] "Kw"  PC,MBMU
 SG_ BAT_Lmt_DisChPwr_53 : 48|16@1+ (0.1,-2000) [-2000|4553.5] "Kw"  PC,MBMU

BO_ 2333540214 S2A_SUMDATA16__54: 8 SBMU
 SG_ BAT_Lmt_ChCurrent_54 : 0|16@1+ (0.1,-2000) [-2000|4553.5] "A"  PC,MBMU
 SG_ BAT_Lmt_DisChCurrent_54 : 16|16@1+ (0.1,-2000) [-2000|4553.5] "A"  PC,MBMU
 SG_ BAT_Lmt_ChPwr_54 : 32|16@1+ (0.1,-2000) [-2000|4553.5] "Kw"  PC,MBMU
 SG_ BAT_Lmt_DisChPwr_54 : 48|16@1+ (0.1,-2000) [-2000|4553.5] "Kw"  PC,MBMU

BO_ 2333540215 S2A_SUMDATA16__55: 8 SBMU
 SG_ BAT_Lmt_ChCurrent_55 : 0|16@1+ (0.1,-2000) [-2000|4553.5] "A"  PC,MBMU
 SG_ BAT_Lmt_DisChCurrent_55 : 16|16@1+ (0.1,-2000) [-2000|4553.5] "A"  PC,MBMU
 SG_ BAT_Lmt_ChPwr_55 : 32|16@1+ (0.1,-2000) [-2000|4553.5] "Kw"  PC,MBMU
 SG_ BAT_Lmt_DisChPwr_55 : 48|16@1+ (0.1,-2000) [-2000|4553.5] "Kw"  PC,MBMU

BO_ 2333540216 S2A_SUMDATA16__56: 8 SBMU
 SG_ BAT_Lmt_ChCurrent_56 : 0|16@1+ (0.1,-2000) [-2000|4553.5] "A"  PC,MBMU
 SG_ BAT_Lmt_DisChCurrent_56 : 16|16@1+ (0.1,-2000) [-2000|4553.5] "A"  PC,MBMU
 SG_ BAT_Lmt_ChPwr_56 : 32|16@1+ (0.1,-2000) [-2000|4553.5] "Kw"  PC,MBMU
 SG_ BAT_Lmt_DisChPwr_56 : 48|16@1+ (0.1,-2000) [-2000|4553.5] "Kw"  PC,MBMU

BO_ 2333540217 S2A_SUMDATA16__57: 8 SBMU
 SG_ BAT_Lmt_ChCurrent_57 : 0|16@1+ (0.1,-2000) [-2000|4553.5] "A"  PC,MBMU
 SG_ BAT_Lmt_DisChCurrent_57 : 16|16@1+ (0.1,-2000) [-2000|4553.5] "A"  PC,MBMU
 SG_ BAT_Lmt_ChPwr_57 : 32|16@1+ (0.1,-2000) [-2000|4553.5] "Kw"  PC,MBMU
 SG_ BAT_Lmt_DisChPwr_57 : 48|16@1+ (0.1,-2000) [-2000|4553.5] "Kw"  PC,MBMU

BO_ 2333540218 S2A_SUMDATA16__58: 8 SBMU
 SG_ BAT_Lmt_ChCurrent_58 : 0|16@1+ (0.1,-2000) [-2000|4553.5] "A"  PC,MBMU
 SG_ BAT_Lmt_DisChCurrent_58 : 16|16@1+ (0.1,-2000) [-2000|4553.5] "A"  PC,MBMU
 SG_ BAT_Lmt_ChPwr_58 : 32|16@1+ (0.1,-2000) [-2000|4553.5] "Kw"  PC,MBMU
 SG_ BAT_Lmt_DisChPwr_58 : 48|16@1+ (0.1,-2000) [-2000|4553.5] "Kw"  PC,MBMU

BO_ 2333540219 S2A_SUMDATA16__59: 8 SBMU
 SG_ BAT_Lmt_ChCurrent_59 : 0|16@1+ (0.1,-2000) [-2000|4553.5] "A"  PC,MBMU
 SG_ BAT_Lmt_DisChCurrent_59 : 16|16@1+ (0.1,-2000) [-2000|4553.5] "A"  PC,MBMU
 SG_ BAT_Lmt_ChPwr_59 : 32|16@1+ (0.1,-2000) [-2000|4553.5] "Kw"  PC,MBMU
 SG_ BAT_Lmt_DisChPwr_59 : 48|16@1+ (0.1,-2000) [-2000|4553.5] "Kw"  PC,MBMU

BO_ 2333540220 S2A_SUMDATA16__60: 8 SBMU
 SG_ BAT_Lmt_ChCurrent_60 : 0|16@1+ (0.1,-2000) [-2000|4553.5] "A"  PC,MBMU
 SG_ BAT_Lmt_DisChCurrent_60 : 16|16@1+ (0.1,-2000) [-2000|4553.5] "A"  PC,MBMU
 SG_ BAT_Lmt_ChPwr_60 : 32|16@1+ (0.1,-2000) [-2000|4553.5] "Kw"  PC,MBMU
 SG_ BAT_Lmt_DisChPwr_60 : 48|16@1+ (0.1,-2000) [-2000|4553.5] "Kw"  PC,MBMU

BO_ 2333540221 S2A_SUMDATA16__61: 8 SBMU
 SG_ BAT_Lmt_ChCurrent_61 : 0|16@1+ (0.1,-2000) [-2000|4553.5] "A"  PC,MBMU
 SG_ BAT_Lmt_DisChCurrent_61 : 16|16@1+ (0.1,-2000) [-2000|4553.5] "A"  PC,MBMU
 SG_ BAT_Lmt_ChPwr_61 : 32|16@1+ (0.1,-2000) [-2000|4553.5] "Kw"  PC,MBMU
 SG_ BAT_Lmt_DisChPwr_61 : 48|16@1+ (0.1,-2000) [-2000|4553.5] "Kw"  PC,MBMU

BO_ 2333540222 S2A_SUMDATA16__62: 8 SBMU
 SG_ BAT_Lmt_ChCurrent_62 : 0|16@1+ (0.1,-2000) [-2000|4553.5] "A"  PC,MBMU
 SG_ BAT_Lmt_DisChCurrent_62 : 16|16@1+ (0.1,-2000) [-2000|4553.5] "A"  PC,MBMU
 SG_ BAT_Lmt_ChPwr_62 : 32|16@1+ (0.1,-2000) [-2000|4553.5] "Kw"  PC,MBMU
 SG_ BAT_Lmt_DisChPwr_62 : 48|16@1+ (0.1,-2000) [-2000|4553.5] "Kw"  PC,MBMU

BO_ 2333540223 S2A_SUMDATA16__63: 8 SBMU
 SG_ BAT_Lmt_ChCurrent_63 : 0|16@1+ (0.1,-2000) [-2000|4553.5] "A"  PC,MBMU
 SG_ BAT_Lmt_DisChCurrent_63 : 16|16@1+ (0.1,-2000) [-2000|4553.5] "A"  PC,MBMU
 SG_ BAT_Lmt_ChPwr_63 : 32|16@1+ (0.1,-2000) [-2000|4553.5] "Kw"  PC,MBMU
 SG_ BAT_Lmt_DisChPwr_63 : 48|16@1+ (0.1,-2000) [-2000|4553.5] "Kw"  PC,MBMU

BO_ 2333605697 S2A_SUMDATA17__01: 8 SBMU
 SG_ S2A_HisOVtimes_01 : 0|16@1+ (1,0) [0|65535] ""  MBMU
 SG_ S2A_HisUVtimes_01 : 16|16@1+ (1,0) [0|65535] ""  MBMU
 SG_ S2A_HisOCCtimes_01 : 32|16@1+ (1,0) [0|65535] ""  MBMU
 SG_ S2A_HisOCDtimes_01 : 48|16@1+ (1,0) [0|65535] ""  MBMU

BO_ 2333605698 S2A_SUMDATA17__02: 8 SBMU
 SG_ S2A_HisOVtimes_02 : 0|16@1+ (1,0) [0|65535] ""  MBMU
 SG_ S2A_HisUVtimes_02 : 16|16@1+ (1,0) [0|65535] ""  MBMU
 SG_ S2A_HisOCCtimes_02 : 32|16@1+ (1,0) [0|65535] ""  MBMU
 SG_ S2A_HisOCDtimes_02 : 48|16@1+ (1,0) [0|65535] ""  MBMU

BO_ 2333605699 S2A_SUMDATA17__03: 8 SBMU
 SG_ S2A_HisOVtimes_03 : 0|16@1+ (1,0) [0|65535] ""  MBMU
 SG_ S2A_HisUVtimes_03 : 16|16@1+ (1,0) [0|65535] ""  MBMU
 SG_ S2A_HisOCCtimes_03 : 32|16@1+ (1,0) [0|65535] ""  MBMU
 SG_ S2A_HisOCDtimes_03 : 48|16@1+ (1,0) [0|65535] ""  MBMU

BO_ 2333605700 S2A_SUMDATA17__04: 8 SBMU
 SG_ S2A_HisOVtimes_04 : 0|16@1+ (1,0) [0|65535] ""  MBMU
 SG_ S2A_HisUVtimes_04 : 16|16@1+ (1,0) [0|65535] ""  MBMU
 SG_ S2A_HisOCCtimes_04 : 32|16@1+ (1,0) [0|65535] ""  MBMU
 SG_ S2A_HisOCDtimes_04 : 48|16@1+ (1,0) [0|65535] ""  MBMU

BO_ 2333605701 S2A_SUMDATA17__05: 8 SBMU
 SG_ S2A_HisOVtimes_05 : 0|16@1+ (1,0) [0|65535] ""  MBMU
 SG_ S2A_HisUVtimes_05 : 16|16@1+ (1,0) [0|65535] ""  MBMU
 SG_ S2A_HisOCCtimes_05 : 32|16@1+ (1,0) [0|65535] ""  MBMU
 SG_ S2A_HisOCDtimes_05 : 48|16@1+ (1,0) [0|65535] ""  MBMU

BO_ 2333605702 S2A_SUMDATA17__06: 8 SBMU
 SG_ S2A_HisOVtimes_06 : 0|16@1+ (1,0) [0|65535] ""  MBMU
 SG_ S2A_HisUVtimes_06 : 16|16@1+ (1,0) [0|65535] ""  MBMU
 SG_ S2A_HisOCCtimes_06 : 32|16@1+ (1,0) [0|65535] ""  MBMU
 SG_ S2A_HisOCDtimes_06 : 48|16@1+ (1,0) [0|65535] ""  MBMU

BO_ 2333605703 S2A_SUMDATA17__07: 8 SBMU
 SG_ S2A_HisOVtimes_07 : 0|16@1+ (1,0) [0|65535] ""  MBMU
 SG_ S2A_HisUVtimes_07 : 16|16@1+ (1,0) [0|65535] ""  MBMU
 SG_ S2A_HisOCCtimes_07 : 32|16@1+ (1,0) [0|65535] ""  MBMU
 SG_ S2A_HisOCDtimes_07 : 48|16@1+ (1,0) [0|65535] ""  MBMU

BO_ 2333605704 S2A_SUMDATA17__08: 8 SBMU
 SG_ S2A_HisOVtimes_08 : 0|16@1+ (1,0) [0|65535] ""  MBMU
 SG_ S2A_HisUVtimes_08 : 16|16@1+ (1,0) [0|65535] ""  MBMU
 SG_ S2A_HisOCCtimes_08 : 32|16@1+ (1,0) [0|65535] ""  MBMU
 SG_ S2A_HisOCDtimes_08 : 48|16@1+ (1,0) [0|65535] ""  MBMU

BO_ 2333605705 S2A_SUMDATA17__09: 8 SBMU
 SG_ S2A_HisOVtimes_09 : 0|16@1+ (1,0) [0|65535] ""  MBMU
 SG_ S2A_HisUVtimes_09 : 16|16@1+ (1,0) [0|65535] ""  MBMU
 SG_ S2A_HisOCCtimes_09 : 32|16@1+ (1,0) [0|65535] ""  MBMU
 SG_ S2A_HisOCDtimes_09 : 48|16@1+ (1,0) [0|65535] ""  MBMU

BO_ 2333605706 S2A_SUMDATA17__10: 8 SBMU
 SG_ S2A_HisOVtimes_10 : 0|16@1+ (1,0) [0|65535] ""  MBMU
 SG_ S2A_HisUVtimes_10 : 16|16@1+ (1,0) [0|65535] ""  MBMU
 SG_ S2A_HisOCCtimes_10 : 32|16@1+ (1,0) [0|65535] ""  MBMU
 SG_ S2A_HisOCDtimes_10 : 48|16@1+ (1,0) [0|65535] ""  MBMU

BO_ 2333605707 S2A_SUMDATA17__11: 8 SBMU
 SG_ S2A_HisOVtimes_11 : 0|16@1+ (1,0) [0|65535] ""  MBMU
 SG_ S2A_HisUVtimes_11 : 16|16@1+ (1,0) [0|65535] ""  MBMU
 SG_ S2A_HisOCCtimes_11 : 32|16@1+ (1,0) [0|65535] ""  MBMU
 SG_ S2A_HisOCDtimes_11 : 48|16@1+ (1,0) [0|65535] ""  MBMU

BO_ 2333605708 S2A_SUMDATA17__12: 8 SBMU
 SG_ S2A_HisOVtimes_12 : 0|16@1+ (1,0) [0|65535] ""  MBMU
 SG_ S2A_HisUVtimes_12 : 16|16@1+ (1,0) [0|65535] ""  MBMU
 SG_ S2A_HisOCCtimes_12 : 32|16@1+ (1,0) [0|65535] ""  MBMU
 SG_ S2A_HisOCDtimes_12 : 48|16@1+ (1,0) [0|65535] ""  MBMU

BO_ 2333605709 S2A_SUMDATA17__13: 8 SBMU
 SG_ S2A_HisOVtimes_13 : 0|16@1+ (1,0) [0|65535] ""  MBMU
 SG_ S2A_HisUVtimes_13 : 16|16@1+ (1,0) [0|65535] ""  MBMU
 SG_ S2A_HisOCCtimes_13 : 32|16@1+ (1,0) [0|65535] ""  MBMU
 SG_ S2A_HisOCDtimes_13 : 48|16@1+ (1,0) [0|65535] ""  MBMU

BO_ 2333605710 S2A_SUMDATA17__14: 8 SBMU
 SG_ S2A_HisOVtimes_14 : 0|16@1+ (1,0) [0|65535] ""  MBMU
 SG_ S2A_HisUVtimes_14 : 16|16@1+ (1,0) [0|65535] ""  MBMU
 SG_ S2A_HisOCCtimes_14 : 32|16@1+ (1,0) [0|65535] ""  MBMU
 SG_ S2A_HisOCDtimes_14 : 48|16@1+ (1,0) [0|65535] ""  MBMU

BO_ 2333605711 S2A_SUMDATA17__15: 8 SBMU
 SG_ S2A_HisOVtimes_15 : 0|16@1+ (1,0) [0|65535] ""  MBMU
 SG_ S2A_HisUVtimes_15 : 16|16@1+ (1,0) [0|65535] ""  MBMU
 SG_ S2A_HisOCCtimes_15 : 32|16@1+ (1,0) [0|65535] ""  MBMU
 SG_ S2A_HisOCDtimes_15 : 48|16@1+ (1,0) [0|65535] ""  MBMU

BO_ 2333605712 S2A_SUMDATA17__16: 8 SBMU
 SG_ S2A_HisOVtimes_16 : 0|16@1+ (1,0) [0|65535] ""  MBMU
 SG_ S2A_HisUVtimes_16 : 16|16@1+ (1,0) [0|65535] ""  MBMU
 SG_ S2A_HisOCCtimes_16 : 32|16@1+ (1,0) [0|65535] ""  MBMU
 SG_ S2A_HisOCDtimes_16 : 48|16@1+ (1,0) [0|65535] ""  MBMU

BO_ 2333605713 S2A_SUMDATA17__17: 8 SBMU
 SG_ S2A_HisOVtimes_17 : 0|16@1+ (1,0) [0|65535] ""  MBMU
 SG_ S2A_HisUVtimes_17 : 16|16@1+ (1,0) [0|65535] ""  MBMU
 SG_ S2A_HisOCCtimes_17 : 32|16@1+ (1,0) [0|65535] ""  MBMU
 SG_ S2A_HisOCDtimes_17 : 48|16@1+ (1,0) [0|65535] ""  MBMU

CM_ SG_ 2333343589 S2A_TRDM_ThrmlRnwyFltCseMsk_37 "热失控原因（每一位代表一种原因）";
CM_ SG_ 2333343589 S2A_TRDM_MaxModuleTempDegC_37 "热失控发生时的最大温度";
CM_ SG_ 2333343589 S2A_TRDM_MinModuleTempDegC_37 "热失控发生时的最小温度";
CM_ SG_ 2333343589 S2A_TRDM_MinCellVoltMv_37 "热失控发生时的最小电芯电压";
CM_ SG_ 2333343589 S2A_TRDM_ThrmlRnwyFltCSC_37 "发生热失控的CSC编号";
CM_ SG_ 2333343590 S2A_TRDM_ThrmlRnwyFltCseMsk_38 "热失控原因（每一位代表一种原因）";
CM_ SG_ 2333343590 S2A_TRDM_MaxModuleTempDegC_38 "热失控发生时的最大温度";
CM_ SG_ 2333343590 S2A_TRDM_MinModuleTempDegC_38 "热失控发生时的最小温度";
CM_ SG_ 2333343590 S2A_TRDM_MinCellVoltMv_38 "热失控发生时的最小电芯电压";
CM_ SG_ 2333343590 S2A_TRDM_ThrmlRnwyFltCSC_38 "发生热失控的CSC编号";
CM_ SG_ 2333343591 S2A_TRDM_ThrmlRnwyFltCseMsk_39 "热失控原因（每一位代表一种原因）";
CM_ SG_ 2333343591 S2A_TRDM_MaxModuleTempDegC_39 "热失控发生时的最大温度";
CM_ SG_ 2333343591 S2A_TRDM_MinModuleTempDegC_39 "热失控发生时的最小温度";
CM_ SG_ 2333343591 S2A_TRDM_MinCellVoltMv_39 "热失控发生时的最小电芯电压";
CM_ SG_ 2333343591 S2A_TRDM_ThrmlRnwyFltCSC_39 "发生热失控的CSC编号";
CM_ SG_ 2333343592 S2A_TRDM_ThrmlRnwyFltCseMsk_40 "热失控原因（每一位代表一种原因）";
CM_ SG_ 2333343592 S2A_TRDM_MaxModuleTempDegC_40 "热失控发生时的最大温度";
CM_ SG_ 2333343592 S2A_TRDM_MinModuleTempDegC_40 "热失控发生时的最小温度";
CM_ SG_ 2333343592 S2A_TRDM_MinCellVoltMv_40 "热失控发生时的最小电芯电压";
CM_ SG_ 2333343592 S2A_TRDM_ThrmlRnwyFltCSC_40 "发生热失控的CSC编号";
CM_ SG_ 2333343593 S2A_TRDM_ThrmlRnwyFltCseMsk_41 "热失控原因（每一位代表一种原因）";
CM_ SG_ 2333343593 S2A_TRDM_MaxModuleTempDegC_41 "热失控发生时的最大温度";
CM_ SG_ 2333343593 S2A_TRDM_MinModuleTempDegC_41 "热失控发生时的最小温度";
CM_ SG_ 2333343593 S2A_TRDM_MinCellVoltMv_41 "热失控发生时的最小电芯电压";
CM_ SG_ 2333343593 S2A_TRDM_ThrmlRnwyFltCSC_41 "发生热失控的CSC编号";
CM_ SG_ 2333343594 S2A_TRDM_ThrmlRnwyFltCseMsk_42 "热失控原因（每一位代表一种原因）";
CM_ SG_ 2333343594 S2A_TRDM_MaxModuleTempDegC_42 "热失控发生时的最大温度";
CM_ SG_ 2333343594 S2A_TRDM_MinModuleTempDegC_42 "热失控发生时的最小温度";
CM_ SG_ 2333343594 S2A_TRDM_MinCellVoltMv_42 "热失控发生时的最小电芯电压";
CM_ SG_ 2333343594 S2A_TRDM_ThrmlRnwyFltCSC_42 "发生热失控的CSC编号";
CM_ SG_ 2333343595 S2A_TRDM_ThrmlRnwyFltCseMsk_43 "热失控原因（每一位代表一种原因）";
CM_ SG_ 2333343595 S2A_TRDM_MaxModuleTempDegC_43 "热失控发生时的最大温度";
CM_ SG_ 2333343595 S2A_TRDM_MinModuleTempDegC_43 "热失控发生时的最小温度";
CM_ SG_ 2333343595 S2A_TRDM_MinCellVoltMv_43 "热失控发生时的最小电芯电压";
CM_ SG_ 2333343595 S2A_TRDM_ThrmlRnwyFltCSC_43 "发生热失控的CSC编号";
CM_ SG_ 2333343596 S2A_TRDM_ThrmlRnwyFltCseMsk_44 "热失控原因（每一位代表一种原因）";
CM_ SG_ 2333343596 S2A_TRDM_MaxModuleTempDegC_44 "热失控发生时的最大温度";
CM_ SG_ 2333343596 S2A_TRDM_MinModuleTempDegC_44 "热失控发生时的最小温度";
CM_ SG_ 2333343596 S2A_TRDM_MinCellVoltMv_44 "热失控发生时的最小电芯电压";
CM_ SG_ 2333343596 S2A_TRDM_ThrmlRnwyFltCSC_44 "发生热失控的CSC编号";
CM_ SG_ 2333343597 S2A_TRDM_ThrmlRnwyFltCseMsk_45 "热失控原因（每一位代表一种原因）";
CM_ SG_ 2333343597 S2A_TRDM_MaxModuleTempDegC_45 "热失控发生时的最大温度";
CM_ SG_ 2333343597 S2A_TRDM_MinModuleTempDegC_45 "热失控发生时的最小温度";
CM_ SG_ 2333343597 S2A_TRDM_MinCellVoltMv_45 "热失控发生时的最小电芯电压";
CM_ SG_ 2333343597 S2A_TRDM_ThrmlRnwyFltCSC_45 "发生热失控的CSC编号";
CM_ SG_ 2333343598 S2A_TRDM_ThrmlRnwyFltCseMsk_46 "热失控原因（每一位代表一种原因）";
CM_ SG_ 2333343598 S2A_TRDM_MaxModuleTempDegC_46 "热失控发生时的最大温度";
CM_ SG_ 2333343598 S2A_TRDM_MinModuleTempDegC_46 "热失控发生时的最小温度";
CM_ SG_ 2333343598 S2A_TRDM_MinCellVoltMv_46 "热失控发生时的最小电芯电压";
CM_ SG_ 2333343598 S2A_TRDM_ThrmlRnwyFltCSC_46 "发生热失控的CSC编号";
CM_ SG_ 2333343599 S2A_TRDM_ThrmlRnwyFltCseMsk_47 "热失控原因（每一位代表一种原因）";
CM_ SG_ 2333343599 S2A_TRDM_MaxModuleTempDegC_47 "热失控发生时的最大温度";
CM_ SG_ 2333343599 S2A_TRDM_MinModuleTempDegC_47 "热失控发生时的最小温度";
CM_ SG_ 2333343599 S2A_TRDM_MinCellVoltMv_47 "热失控发生时的最小电芯电压";
CM_ SG_ 2333343599 S2A_TRDM_ThrmlRnwyFltCSC_47 "发生热失控的CSC编号";
CM_ SG_ 2333343600 S2A_TRDM_ThrmlRnwyFltCseMsk_48 "热失控原因（每一位代表一种原因）";
CM_ SG_ 2333343600 S2A_TRDM_MaxModuleTempDegC_48 "热失控发生时的最大温度";
CM_ SG_ 2333343600 S2A_TRDM_MinModuleTempDegC_48 "热失控发生时的最小温度";
CM_ SG_ 2333343600 S2A_TRDM_MinCellVoltMv_48 "热失控发生时的最小电芯电压";
CM_ SG_ 2333343600 S2A_TRDM_ThrmlRnwyFltCSC_48 "发生热失控的CSC编号";
CM_ SG_ 2333343601 S2A_TRDM_ThrmlRnwyFltCseMsk_49 "热失控原因（每一位代表一种原因）";
CM_ SG_ 2333343601 S2A_TRDM_MaxModuleTempDegC_49 "热失控发生时的最大温度";
CM_ SG_ 2333343601 S2A_TRDM_MinModuleTempDegC_49 "热失控发生时的最小温度";
CM_ SG_ 2333343601 S2A_TRDM_MinCellVoltMv_49 "热失控发生时的最小电芯电压";
CM_ SG_ 2333343601 S2A_TRDM_ThrmlRnwyFltCSC_49 "发生热失控的CSC编号";
CM_ SG_ 2333343602 S2A_TRDM_ThrmlRnwyFltCseMsk_50 "热失控原因（每一位代表一种原因）";
CM_ SG_ 2333343602 S2A_TRDM_MaxModuleTempDegC_50 "热失控发生时的最大温度";
CM_ SG_ 2333343602 S2A_TRDM_MinModuleTempDegC_50 "热失控发生时的最小温度";
CM_ SG_ 2333343602 S2A_TRDM_MinCellVoltMv_50 "热失控发生时的最小电芯电压";
CM_ SG_ 2333343602 S2A_TRDM_ThrmlRnwyFltCSC_50 "发生热失控的CSC编号";
CM_ SG_ 2333343603 S2A_TRDM_ThrmlRnwyFltCseMsk_51 "热失控原因（每一位代表一种原因）";
CM_ SG_ 2333343603 S2A_TRDM_MaxModuleTempDegC_51 "热失控发生时的最大温度";
CM_ SG_ 2333343603 S2A_TRDM_MinModuleTempDegC_51 "热失控发生时的最小温度";
CM_ SG_ 2333343603 S2A_TRDM_MinCellVoltMv_51 "热失控发生时的最小电芯电压";
CM_ SG_ 2333343603 S2A_TRDM_ThrmlRnwyFltCSC_51 "发生热失控的CSC编号";
CM_ SG_ 2333343604 S2A_TRDM_ThrmlRnwyFltCseMsk_52 "热失控原因（每一位代表一种原因）";
CM_ SG_ 2333343604 S2A_TRDM_MaxModuleTempDegC_52 "热失控发生时的最大温度";
CM_ SG_ 2333343604 S2A_TRDM_MinModuleTempDegC_52 "热失控发生时的最小温度";
CM_ SG_ 2333343604 S2A_TRDM_MinCellVoltMv_52 "热失控发生时的最小电芯电压";
CM_ SG_ 2333343604 S2A_TRDM_ThrmlRnwyFltCSC_52 "发生热失控的CSC编号";
CM_ SG_ 2333343605 S2A_TRDM_ThrmlRnwyFltCseMsk_53 "热失控原因（每一位代表一种原因）";
CM_ SG_ 2333343605 S2A_TRDM_MaxModuleTempDegC_53 "热失控发生时的最大温度";
CM_ SG_ 2333343605 S2A_TRDM_MinModuleTempDegC_53 "热失控发生时的最小温度";
CM_ SG_ 2333343605 S2A_TRDM_MinCellVoltMv_53 "热失控发生时的最小电芯电压";
CM_ SG_ 2333343605 S2A_TRDM_ThrmlRnwyFltCSC_53 "发生热失控的CSC编号";
CM_ SG_ 2333343606 S2A_TRDM_ThrmlRnwyFltCseMsk_54 "热失控原因（每一位代表一种原因）";
CM_ SG_ 2333343606 S2A_TRDM_MaxModuleTempDegC_54 "热失控发生时的最大温度";
CM_ SG_ 2333343606 S2A_TRDM_MinModuleTempDegC_54 "热失控发生时的最小温度";
CM_ SG_ 2333343606 S2A_TRDM_MinCellVoltMv_54 "热失控发生时的最小电芯电压";
CM_ SG_ 2333343606 S2A_TRDM_ThrmlRnwyFltCSC_54 "发生热失控的CSC编号";
CM_ SG_ 2333343607 S2A_TRDM_ThrmlRnwyFltCseMsk_55 "热失控原因（每一位代表一种原因）";
CM_ SG_ 2333343607 S2A_TRDM_MaxModuleTempDegC_55 "热失控发生时的最大温度";
CM_ SG_ 2333343607 S2A_TRDM_MinModuleTempDegC_55 "热失控发生时的最小温度";
CM_ SG_ 2333343607 S2A_TRDM_MinCellVoltMv_55 "热失控发生时的最小电芯电压";
CM_ SG_ 2333343607 S2A_TRDM_ThrmlRnwyFltCSC_55 "发生热失控的CSC编号";
CM_ SG_ 2333343608 S2A_TRDM_ThrmlRnwyFltCseMsk_56 "热失控原因（每一位代表一种原因）";
CM_ SG_ 2333343608 S2A_TRDM_MaxModuleTempDegC_56 "热失控发生时的最大温度";
CM_ SG_ 2333343608 S2A_TRDM_MinModuleTempDegC_56 "热失控发生时的最小温度";
CM_ SG_ 2333343608 S2A_TRDM_MinCellVoltMv_56 "热失控发生时的最小电芯电压";
CM_ SG_ 2333343608 S2A_TRDM_ThrmlRnwyFltCSC_56 "发生热失控的CSC编号";
CM_ SG_ 2333343609 S2A_TRDM_ThrmlRnwyFltCseMsk_57 "热失控原因（每一位代表一种原因）";
CM_ SG_ 2333343609 S2A_TRDM_MaxModuleTempDegC_57 "热失控发生时的最大温度";
CM_ SG_ 2333343609 S2A_TRDM_MinModuleTempDegC_57 "热失控发生时的最小温度";
CM_ SG_ 2333343609 S2A_TRDM_MinCellVoltMv_57 "热失控发生时的最小电芯电压";
CM_ SG_ 2333343609 S2A_TRDM_ThrmlRnwyFltCSC_57 "发生热失控的CSC编号";
CM_ SG_ 2333343610 S2A_TRDM_ThrmlRnwyFltCseMsk_58 "热失控原因（每一位代表一种原因）";
CM_ SG_ 2333343610 S2A_TRDM_MaxModuleTempDegC_58 "热失控发生时的最大温度";
CM_ SG_ 2333343610 S2A_TRDM_MinModuleTempDegC_58 "热失控发生时的最小温度";
CM_ SG_ 2333343610 S2A_TRDM_MinCellVoltMv_58 "热失控发生时的最小电芯电压";
CM_ SG_ 2333343610 S2A_TRDM_ThrmlRnwyFltCSC_58 "发生热失控的CSC编号";
CM_ SG_ 2333343611 S2A_TRDM_ThrmlRnwyFltCseMsk_59 "热失控原因（每一位代表一种原因）";
CM_ SG_ 2333343611 S2A_TRDM_MaxModuleTempDegC_59 "热失控发生时的最大温度";
CM_ SG_ 2333343611 S2A_TRDM_MinModuleTempDegC_59 "热失控发生时的最小温度";
CM_ SG_ 2333343611 S2A_TRDM_MinCellVoltMv_59 "热失控发生时的最小电芯电压";
CM_ SG_ 2333343611 S2A_TRDM_ThrmlRnwyFltCSC_59 "发生热失控的CSC编号";
CM_ SG_ 2333343612 S2A_TRDM_ThrmlRnwyFltCseMsk_60 "热失控原因（每一位代表一种原因）";
CM_ SG_ 2333343612 S2A_TRDM_MaxModuleTempDegC_60 "热失控发生时的最大温度";
CM_ SG_ 2333343612 S2A_TRDM_MinModuleTempDegC_60 "热失控发生时的最小温度";
CM_ SG_ 2333343612 S2A_TRDM_MinCellVoltMv_60 "热失控发生时的最小电芯电压";
CM_ SG_ 2333343612 S2A_TRDM_ThrmlRnwyFltCSC_60 "发生热失控的CSC编号";
CM_ SG_ 2333343613 S2A_TRDM_ThrmlRnwyFltCseMsk_61 "热失控原因（每一位代表一种原因）";
CM_ SG_ 2333343613 S2A_TRDM_MaxModuleTempDegC_61 "热失控发生时的最大温度";
CM_ SG_ 2333343613 S2A_TRDM_MinModuleTempDegC_61 "热失控发生时的最小温度";
CM_ SG_ 2333343613 S2A_TRDM_MinCellVoltMv_61 "热失控发生时的最小电芯电压";
CM_ SG_ 2333343613 S2A_TRDM_ThrmlRnwyFltCSC_61 "发生热失控的CSC编号";
CM_ SG_ 2333343614 S2A_TRDM_ThrmlRnwyFltCseMsk_62 "热失控原因（每一位代表一种原因）";
CM_ SG_ 2333343614 S2A_TRDM_MaxModuleTempDegC_62 "热失控发生时的最大温度";
CM_ SG_ 2333343614 S2A_TRDM_MinModuleTempDegC_62 "热失控发生时的最小温度";
CM_ SG_ 2333343614 S2A_TRDM_MinCellVoltMv_62 "热失控发生时的最小电芯电压";
CM_ SG_ 2333343614 S2A_TRDM_ThrmlRnwyFltCSC_62 "发生热失控的CSC编号";
CM_ SG_ 2333343615 S2A_TRDM_ThrmlRnwyFltCseMsk_63 "热失控原因（每一位代表一种原因）";
CM_ SG_ 2333343615 S2A_TRDM_MaxModuleTempDegC_63 "热失控发生时的最大温度";
CM_ SG_ 2333343615 S2A_TRDM_MinModuleTempDegC_63 "热失控发生时的最小温度";
CM_ SG_ 2333343615 S2A_TRDM_MinCellVoltMv_63 "热失控发生时的最小电芯电压";
CM_ SG_ 2333343615 S2A_TRDM_ThrmlRnwyFltCSC_63 "发生热失控的CSC编号";
CM_ SG_ 2333409089 CRC_S2A_S14_01 "S2A概要数据14 的CRC";
CM_ SG_ 2333409089 S2A_SUMDATA14_Reserve_01 "预留";
CM_ SG_ 2333409089 BAT_Tpole_Max_01 "最高电极温度";
CM_ SG_ 2333409089 BAT_Tpole_Min_01 "最低电极温度";
CM_ SG_ 2333409089 BAT_Tpole_Avg_01 "平均电极温度";
CM_ SG_ 2333409089 BAT_Tpole_Max_CSC_01 "最高电极温度所在CSC号";
CM_ SG_ 2333409089 BAT_Tpole_Min_CSC_01 "最低电极温度所在CSC号";
CM_ SG_ 2333409090 CRC_S2A_S14_02 "S2A概要数据14 的CRC";
CM_ SG_ 2333409090 S2A_SUMDATA14_Reserve_02 "预留";
CM_ SG_ 2333409090 BAT_Tpole_Max_02 "最高电极温度";
CM_ SG_ 2333409090 BAT_Tpole_Min_02 "最低电极温度";
CM_ SG_ 2333409090 BAT_Tpole_Avg_02 "平均电极温度";
CM_ SG_ 2333409090 BAT_Tpole_Max_CSC_02 "最高电极温度所在CSC号";
CM_ SG_ 2333409090 BAT_Tpole_Min_CSC_02 "最低电极温度所在CSC号";
CM_ SG_ 2333409091 CRC_S2A_S14_03 "S2A概要数据14 的CRC";
CM_ SG_ 2333409091 S2A_SUMDATA14_Reserve_03 "预留";
CM_ SG_ 2333409091 BAT_Tpole_Max_03 "最高电极温度";
CM_ SG_ 2333409091 BAT_Tpole_Min_03 "最低电极温度";
CM_ SG_ 2333409091 BAT_Tpole_Avg_03 "平均电极温度";
CM_ SG_ 2333409091 BAT_Tpole_Max_CSC_03 "最高电极温度所在CSC号";
CM_ SG_ 2333409091 BAT_Tpole_Min_CSC_03 "最低电极温度所在CSC号";
CM_ SG_ 2333409092 CRC_S2A_S14_04 "S2A概要数据14 的CRC";
CM_ SG_ 2333409092 S2A_SUMDATA14_Reserve_04 "预留";
CM_ SG_ 2333409092 BAT_Tpole_Max_04 "最高电极温度";
CM_ SG_ 2333409092 BAT_Tpole_Min_04 "最低电极温度";
CM_ SG_ 2333409092 BAT_Tpole_Avg_04 "平均电极温度";
CM_ SG_ 2333409092 BAT_Tpole_Max_CSC_04 "最高电极温度所在CSC号";
CM_ SG_ 2333409092 BAT_Tpole_Min_CSC_04 "最低电极温度所在CSC号";
CM_ SG_ 2333409093 CRC_S2A_S14_05 "S2A概要数据14 的CRC";
CM_ SG_ 2333409093 S2A_SUMDATA14_Reserve_05 "预留";
CM_ SG_ 2333409093 BAT_Tpole_Max_05 "最高电极温度";
CM_ SG_ 2333409093 BAT_Tpole_Min_05 "最低电极温度";
CM_ SG_ 2333409093 BAT_Tpole_Avg_05 "平均电极温度";
CM_ SG_ 2333409093 BAT_Tpole_Max_CSC_05 "最高电极温度所在CSC号";
CM_ SG_ 2333409093 BAT_Tpole_Min_CSC_05 "最低电极温度所在CSC号";
CM_ SG_ 2333409094 CRC_S2A_S14_06 "S2A概要数据14 的CRC";
CM_ SG_ 2333409094 S2A_SUMDATA14_Reserve_06 "预留";
CM_ SG_ 2333409094 BAT_Tpole_Max_06 "最高电极温度";
CM_ SG_ 2333409094 BAT_Tpole_Min_06 "最低电极温度";
CM_ SG_ 2333409094 BAT_Tpole_Avg_06 "平均电极温度";
CM_ SG_ 2333409094 BAT_Tpole_Max_CSC_06 "最高电极温度所在CSC号";
CM_ SG_ 2333409094 BAT_Tpole_Min_CSC_06 "最低电极温度所在CSC号";
CM_ SG_ 2333409095 CRC_S2A_S14_07 "S2A概要数据14 的CRC";
CM_ SG_ 2333409095 S2A_SUMDATA14_Reserve_07 "预留";
CM_ SG_ 2333409095 BAT_Tpole_Max_07 "最高电极温度";
CM_ SG_ 2333409095 BAT_Tpole_Min_07 "最低电极温度";
CM_ SG_ 2333409095 BAT_Tpole_Avg_07 "平均电极温度";
CM_ SG_ 2333409095 BAT_Tpole_Max_CSC_07 "最高电极温度所在CSC号";
CM_ SG_ 2333409095 BAT_Tpole_Min_CSC_07 "最低电极温度所在CSC号";
CM_ SG_ 2333409096 CRC_S2A_S14_08 "S2A概要数据14 的CRC";
CM_ SG_ 2333409096 S2A_SUMDATA14_Reserve_08 "预留";
CM_ SG_ 2333409096 BAT_Tpole_Max_08 "最高电极温度";
CM_ SG_ 2333409096 BAT_Tpole_Min_08 "最低电极温度";
CM_ SG_ 2333409096 BAT_Tpole_Avg_08 "平均电极温度";
CM_ SG_ 2333409096 BAT_Tpole_Max_CSC_08 "最高电极温度所在CSC号";
CM_ SG_ 2333409096 BAT_Tpole_Min_CSC_08 "最低电极温度所在CSC号";
CM_ SG_ 2333409097 CRC_S2A_S14_09 "S2A概要数据14 的CRC";
CM_ SG_ 2333409097 S2A_SUMDATA14_Reserve_09 "预留";
CM_ SG_ 2333409097 BAT_Tpole_Max_09 "最高电极温度";
CM_ SG_ 2333409097 BAT_Tpole_Min_09 "最低电极温度";
CM_ SG_ 2333409097 BAT_Tpole_Avg_09 "平均电极温度";
CM_ SG_ 2333409097 BAT_Tpole_Max_CSC_09 "最高电极温度所在CSC号";
CM_ SG_ 2333409097 BAT_Tpole_Min_CSC_09 "最低电极温度所在CSC号";
CM_ SG_ 2333409098 CRC_S2A_S14_10 "S2A概要数据14 的CRC";
CM_ SG_ 2333409098 S2A_SUMDATA14_Reserve_10 "预留";
CM_ SG_ 2333409098 BAT_Tpole_Max_10 "最高电极温度";
CM_ SG_ 2333409098 BAT_Tpole_Min_10 "最低电极温度";
CM_ SG_ 2333409098 BAT_Tpole_Avg_10 "平均电极温度";
CM_ SG_ 2333409098 BAT_Tpole_Max_CSC_10 "最高电极温度所在CSC号";
CM_ SG_ 2333409098 BAT_Tpole_Min_CSC_10 "最低电极温度所在CSC号";
CM_ SG_ 2333409099 CRC_S2A_S14_11 "S2A概要数据14 的CRC";
CM_ SG_ 2333409099 S2A_SUMDATA14_Reserve_11 "预留";
CM_ SG_ 2333409099 BAT_Tpole_Max_11 "最高电极温度";
CM_ SG_ 2333409099 BAT_Tpole_Min_11 "最低电极温度";
CM_ SG_ 2333409099 BAT_Tpole_Avg_11 "平均电极温度";
CM_ SG_ 2333409099 BAT_Tpole_Max_CSC_11 "最高电极温度所在CSC号";
CM_ SG_ 2333409099 BAT_Tpole_Min_CSC_11 "最低电极温度所在CSC号";
CM_ SG_ 2333409100 CRC_S2A_S14_12 "S2A概要数据14 的CRC";
CM_ SG_ 2333409100 S2A_SUMDATA14_Reserve_12 "预留";
CM_ SG_ 2333409100 BAT_Tpole_Max_12 "最高电极温度";
CM_ SG_ 2333409100 BAT_Tpole_Min_12 "最低电极温度";
CM_ SG_ 2333409100 BAT_Tpole_Avg_12 "平均电极温度";
CM_ SG_ 2333409100 BAT_Tpole_Max_CSC_12 "最高电极温度所在CSC号";
CM_ SG_ 2333409100 BAT_Tpole_Min_CSC_12 "最低电极温度所在CSC号";
CM_ SG_ 2333409101 CRC_S2A_S14_13 "S2A概要数据14 的CRC";
CM_ SG_ 2333409101 S2A_SUMDATA14_Reserve_13 "预留";
CM_ SG_ 2333409101 BAT_Tpole_Max_13 "最高电极温度";
CM_ SG_ 2333409101 BAT_Tpole_Min_13 "最低电极温度";
CM_ SG_ 2333409101 BAT_Tpole_Avg_13 "平均电极温度";
CM_ SG_ 2333409101 BAT_Tpole_Max_CSC_13 "最高电极温度所在CSC号";
CM_ SG_ 2333409101 BAT_Tpole_Min_CSC_13 "最低电极温度所在CSC号";
CM_ SG_ 2333409102 CRC_S2A_S14_14 "S2A概要数据14 的CRC";
CM_ SG_ 2333409102 S2A_SUMDATA14_Reserve_14 "预留";
CM_ SG_ 2333409102 BAT_Tpole_Max_14 "最高电极温度";
CM_ SG_ 2333409102 BAT_Tpole_Min_14 "最低电极温度";
CM_ SG_ 2333409102 BAT_Tpole_Avg_14 "平均电极温度";
CM_ SG_ 2333409102 BAT_Tpole_Max_CSC_14 "最高电极温度所在CSC号";
CM_ SG_ 2333409102 BAT_Tpole_Min_CSC_14 "最低电极温度所在CSC号";
CM_ SG_ 2333409103 CRC_S2A_S14_15 "S2A概要数据14 的CRC";
CM_ SG_ 2333409103 S2A_SUMDATA14_Reserve_15 "预留";
CM_ SG_ 2333409103 BAT_Tpole_Max_15 "最高电极温度";
CM_ SG_ 2333409103 BAT_Tpole_Min_15 "最低电极温度";
CM_ SG_ 2333409103 BAT_Tpole_Avg_15 "平均电极温度";
CM_ SG_ 2333409103 BAT_Tpole_Max_CSC_15 "最高电极温度所在CSC号";
CM_ SG_ 2333409103 BAT_Tpole_Min_CSC_15 "最低电极温度所在CSC号";
CM_ SG_ 2333409104 CRC_S2A_S14_16 "S2A概要数据14 的CRC";
CM_ SG_ 2333409104 S2A_SUMDATA14_Reserve_16 "预留";
CM_ SG_ 2333409104 BAT_Tpole_Max_16 "最高电极温度";
CM_ SG_ 2333409104 BAT_Tpole_Min_16 "最低电极温度";
CM_ SG_ 2333409104 BAT_Tpole_Avg_16 "平均电极温度";
CM_ SG_ 2333409104 BAT_Tpole_Max_CSC_16 "最高电极温度所在CSC号";
CM_ SG_ 2333409104 BAT_Tpole_Min_CSC_16 "最低电极温度所在CSC号";
CM_ SG_ 2333409105 CRC_S2A_S14_17 "S2A概要数据14 的CRC";
CM_ SG_ 2333409105 S2A_SUMDATA14_Reserve_17 "预留";
CM_ SG_ 2333409105 BAT_Tpole_Max_17 "最高电极温度";
CM_ SG_ 2333409105 BAT_Tpole_Min_17 "最低电极温度";
CM_ SG_ 2333409105 BAT_Tpole_Avg_17 "平均电极温度";
CM_ SG_ 2333409105 BAT_Tpole_Max_CSC_17 "最高电极温度所在CSC号";
CM_ SG_ 2333409105 BAT_Tpole_Min_CSC_17 "最低电极温度所在CSC号";
CM_ SG_ 2333409106 CRC_S2A_S14_18 "S2A概要数据14 的CRC";
CM_ SG_ 2333409106 S2A_SUMDATA14_Reserve_18 "预留";
CM_ SG_ 2333409106 BAT_Tpole_Max_18 "最高电极温度";
CM_ SG_ 2333409106 BAT_Tpole_Min_18 "最低电极温度";
CM_ SG_ 2333409106 BAT_Tpole_Avg_18 "平均电极温度";
CM_ SG_ 2333409106 BAT_Tpole_Max_CSC_18 "最高电极温度所在CSC号";
CM_ SG_ 2333409106 BAT_Tpole_Min_CSC_18 "最低电极温度所在CSC号";
CM_ SG_ 2333409107 CRC_S2A_S14_19 "S2A概要数据14 的CRC";
CM_ SG_ 2333409107 S2A_SUMDATA14_Reserve_19 "预留";
CM_ SG_ 2333409107 BAT_Tpole_Max_19 "最高电极温度";
CM_ SG_ 2333409107 BAT_Tpole_Min_19 "最低电极温度";
CM_ SG_ 2333409107 BAT_Tpole_Avg_19 "平均电极温度";
CM_ SG_ 2333409107 BAT_Tpole_Max_CSC_19 "最高电极温度所在CSC号";
CM_ SG_ 2333409107 BAT_Tpole_Min_CSC_19 "最低电极温度所在CSC号";
CM_ SG_ 2333409108 CRC_S2A_S14_20 "S2A概要数据14 的CRC";
CM_ SG_ 2333409108 S2A_SUMDATA14_Reserve_20 "预留";
CM_ SG_ 2333409108 BAT_Tpole_Max_20 "最高电极温度";
CM_ SG_ 2333409108 BAT_Tpole_Min_20 "最低电极温度";
CM_ SG_ 2333409108 BAT_Tpole_Avg_20 "平均电极温度";
CM_ SG_ 2333409108 BAT_Tpole_Max_CSC_20 "最高电极温度所在CSC号";
CM_ SG_ 2333409108 BAT_Tpole_Min_CSC_20 "最低电极温度所在CSC号";
CM_ SG_ 2333409109 CRC_S2A_S14_21 "S2A概要数据14 的CRC";
CM_ SG_ 2333409109 S2A_SUMDATA14_Reserve_21 "预留";
CM_ SG_ 2333409109 BAT_Tpole_Max_21 "最高电极温度";
CM_ SG_ 2333409109 BAT_Tpole_Min_21 "最低电极温度";
CM_ SG_ 2333409109 BAT_Tpole_Avg_21 "平均电极温度";
CM_ SG_ 2333409109 BAT_Tpole_Max_CSC_21 "最高电极温度所在CSC号";
CM_ SG_ 2333409109 BAT_Tpole_Min_CSC_21 "最低电极温度所在CSC号";
CM_ SG_ 2333409110 CRC_S2A_S14_22 "S2A概要数据14 的CRC";
CM_ SG_ 2333409110 S2A_SUMDATA14_Reserve_22 "预留";
CM_ SG_ 2333409110 BAT_Tpole_Max_22 "最高电极温度";
CM_ SG_ 2333409110 BAT_Tpole_Min_22 "最低电极温度";
CM_ SG_ 2333409110 BAT_Tpole_Avg_22 "平均电极温度";
CM_ SG_ 2333409110 BAT_Tpole_Max_CSC_22 "最高电极温度所在CSC号";
CM_ SG_ 2333409110 BAT_Tpole_Min_CSC_22 "最低电极温度所在CSC号";
CM_ SG_ 2333409111 CRC_S2A_S14_23 "S2A概要数据14 的CRC";
CM_ SG_ 2333409111 S2A_SUMDATA14_Reserve_23 "预留";
CM_ SG_ 2333409111 BAT_Tpole_Max_23 "最高电极温度";
CM_ SG_ 2333409111 BAT_Tpole_Min_23 "最低电极温度";
CM_ SG_ 2333409111 BAT_Tpole_Avg_23 "平均电极温度";
CM_ SG_ 2333409111 BAT_Tpole_Max_CSC_23 "最高电极温度所在CSC号";
CM_ SG_ 2333409111 BAT_Tpole_Min_CSC_23 "最低电极温度所在CSC号";
CM_ SG_ 2333409112 CRC_S2A_S14_24 "S2A概要数据14 的CRC";
CM_ SG_ 2333409112 S2A_SUMDATA14_Reserve_24 "预留";
CM_ SG_ 2333409112 BAT_Tpole_Max_24 "最高电极温度";
CM_ SG_ 2333409112 BAT_Tpole_Min_24 "最低电极温度";
CM_ SG_ 2333409112 BAT_Tpole_Avg_24 "平均电极温度";
CM_ SG_ 2333409112 BAT_Tpole_Max_CSC_24 "最高电极温度所在CSC号";
CM_ SG_ 2333409112 BAT_Tpole_Min_CSC_24 "最低电极温度所在CSC号";
CM_ SG_ 2333409113 CRC_S2A_S14_25 "S2A概要数据14 的CRC";
CM_ SG_ 2333409113 S2A_SUMDATA14_Reserve_25 "预留";
CM_ SG_ 2333409113 BAT_Tpole_Max_25 "最高电极温度";
CM_ SG_ 2333409113 BAT_Tpole_Min_25 "最低电极温度";
CM_ SG_ 2333409113 BAT_Tpole_Avg_25 "平均电极温度";
CM_ SG_ 2333409113 BAT_Tpole_Max_CSC_25 "最高电极温度所在CSC号";
CM_ SG_ 2333409113 BAT_Tpole_Min_CSC_25 "最低电极温度所在CSC号";
CM_ SG_ 2333409114 CRC_S2A_S14_26 "S2A概要数据14 的CRC";
CM_ SG_ 2333409114 S2A_SUMDATA14_Reserve_26 "预留";
CM_ SG_ 2333409114 BAT_Tpole_Max_26 "最高电极温度";
CM_ SG_ 2333409114 BAT_Tpole_Min_26 "最低电极温度";
CM_ SG_ 2333409114 BAT_Tpole_Avg_26 "平均电极温度";
CM_ SG_ 2333409114 BAT_Tpole_Max_CSC_26 "最高电极温度所在CSC号";
CM_ SG_ 2333409114 BAT_Tpole_Min_CSC_26 "最低电极温度所在CSC号";
CM_ SG_ 2333409115 CRC_S2A_S14_27 "S2A概要数据14 的CRC";
CM_ SG_ 2333409115 S2A_SUMDATA14_Reserve_27 "预留";
CM_ SG_ 2333409115 BAT_Tpole_Max_27 "最高电极温度";
CM_ SG_ 2333409115 BAT_Tpole_Min_27 "最低电极温度";
CM_ SG_ 2333409115 BAT_Tpole_Avg_27 "平均电极温度";
CM_ SG_ 2333409115 BAT_Tpole_Max_CSC_27 "最高电极温度所在CSC号";
CM_ SG_ 2333409115 BAT_Tpole_Min_CSC_27 "最低电极温度所在CSC号";
CM_ SG_ 2333409116 CRC_S2A_S14_28 "S2A概要数据14 的CRC";
CM_ SG_ 2333409116 S2A_SUMDATA14_Reserve_28 "预留";
CM_ SG_ 2333409116 BAT_Tpole_Max_28 "最高电极温度";
CM_ SG_ 2333409116 BAT_Tpole_Min_28 "最低电极温度";
CM_ SG_ 2333409116 BAT_Tpole_Avg_28 "平均电极温度";
CM_ SG_ 2333409116 BAT_Tpole_Max_CSC_28 "最高电极温度所在CSC号";
CM_ SG_ 2333409116 BAT_Tpole_Min_CSC_28 "最低电极温度所在CSC号";
CM_ SG_ 2333409117 CRC_S2A_S14_29 "S2A概要数据14 的CRC";
CM_ SG_ 2333409117 S2A_SUMDATA14_Reserve_29 "预留";
CM_ SG_ 2333409117 BAT_Tpole_Max_29 "最高电极温度";
CM_ SG_ 2333409117 BAT_Tpole_Min_29 "最低电极温度";
CM_ SG_ 2333409117 BAT_Tpole_Avg_29 "平均电极温度";
CM_ SG_ 2333409117 BAT_Tpole_Max_CSC_29 "最高电极温度所在CSC号";
CM_ SG_ 2333409117 BAT_Tpole_Min_CSC_29 "最低电极温度所在CSC号";
CM_ SG_ 2333409118 CRC_S2A_S14_30 "S2A概要数据14 的CRC";
CM_ SG_ 2333409118 S2A_SUMDATA14_Reserve_30 "预留";
CM_ SG_ 2333409118 BAT_Tpole_Max_30 "最高电极温度";
CM_ SG_ 2333409118 BAT_Tpole_Min_30 "最低电极温度";
CM_ SG_ 2333409118 BAT_Tpole_Avg_30 "平均电极温度";
CM_ SG_ 2333409118 BAT_Tpole_Max_CSC_30 "最高电极温度所在CSC号";
CM_ SG_ 2333409118 BAT_Tpole_Min_CSC_30 "最低电极温度所在CSC号";
CM_ SG_ 2333409119 CRC_S2A_S14_31 "S2A概要数据14 的CRC";
CM_ SG_ 2333409119 S2A_SUMDATA14_Reserve_31 "预留";
CM_ SG_ 2333409119 BAT_Tpole_Max_31 "最高电极温度";
CM_ SG_ 2333409119 BAT_Tpole_Min_31 "最低电极温度";
CM_ SG_ 2333409119 BAT_Tpole_Avg_31 "平均电极温度";
CM_ SG_ 2333409119 BAT_Tpole_Max_CSC_31 "最高电极温度所在CSC号";
CM_ SG_ 2333409119 BAT_Tpole_Min_CSC_31 "最低电极温度所在CSC号";
CM_ SG_ 2333409120 CRC_S2A_S14_32 "S2A概要数据14 的CRC";
CM_ SG_ 2333409120 S2A_SUMDATA14_Reserve_32 "预留";
CM_ SG_ 2333409120 BAT_Tpole_Max_32 "最高电极温度";
CM_ SG_ 2333409120 BAT_Tpole_Min_32 "最低电极温度";
CM_ SG_ 2333409120 BAT_Tpole_Avg_32 "平均电极温度";
CM_ SG_ 2333409120 BAT_Tpole_Max_CSC_32 "最高电极温度所在CSC号";
CM_ SG_ 2333409120 BAT_Tpole_Min_CSC_32 "最低电极温度所在CSC号";
CM_ SG_ 2333409121 CRC_S2A_S14_33 "S2A概要数据14 的CRC";
CM_ SG_ 2333409121 S2A_SUMDATA14_Reserve_33 "预留";
CM_ SG_ 2333409121 BAT_Tpole_Max_33 "最高电极温度";
CM_ SG_ 2333409121 BAT_Tpole_Min_33 "最低电极温度";
CM_ SG_ 2333409121 BAT_Tpole_Avg_33 "平均电极温度";
CM_ SG_ 2333409121 BAT_Tpole_Max_CSC_33 "最高电极温度所在CSC号";
CM_ SG_ 2333409121 BAT_Tpole_Min_CSC_33 "最低电极温度所在CSC号";
CM_ SG_ 2333409122 CRC_S2A_S14_34 "S2A概要数据14 的CRC";
CM_ SG_ 2333409122 S2A_SUMDATA14_Reserve_34 "预留";
CM_ SG_ 2333409122 BAT_Tpole_Max_34 "最高电极温度";
CM_ SG_ 2333409122 BAT_Tpole_Min_34 "最低电极温度";
CM_ SG_ 2333409122 BAT_Tpole_Avg_34 "平均电极温度";
CM_ SG_ 2333409122 BAT_Tpole_Max_CSC_34 "最高电极温度所在CSC号";
CM_ SG_ 2333409122 BAT_Tpole_Min_CSC_34 "最低电极温度所在CSC号";
CM_ SG_ 2333409123 CRC_S2A_S14_35 "S2A概要数据14 的CRC";
CM_ SG_ 2333409123 S2A_SUMDATA14_Reserve_35 "预留";
CM_ SG_ 2333409123 BAT_Tpole_Max_35 "最高电极温度";
CM_ SG_ 2333409123 BAT_Tpole_Min_35 "最低电极温度";
CM_ SG_ 2333409123 BAT_Tpole_Avg_35 "平均电极温度";
CM_ SG_ 2333409123 BAT_Tpole_Max_CSC_35 "最高电极温度所在CSC号";
CM_ SG_ 2333409123 BAT_Tpole_Min_CSC_35 "最低电极温度所在CSC号";
CM_ SG_ 2333409124 CRC_S2A_S14_36 "S2A概要数据14 的CRC";
CM_ SG_ 2333409124 S2A_SUMDATA14_Reserve_36 "预留";
CM_ SG_ 2333409124 BAT_Tpole_Max_36 "最高电极温度";
CM_ SG_ 2333409124 BAT_Tpole_Min_36 "最低电极温度";
CM_ SG_ 2333409124 BAT_Tpole_Avg_36 "平均电极温度";
CM_ SG_ 2333409124 BAT_Tpole_Max_CSC_36 "最高电极温度所在CSC号";
CM_ SG_ 2333409124 BAT_Tpole_Min_CSC_36 "最低电极温度所在CSC号";
CM_ SG_ 2333409125 CRC_S2A_S14_37 "S2A概要数据14 的CRC";
CM_ SG_ 2333409125 S2A_SUMDATA14_Reserve_37 "预留";
CM_ SG_ 2333409125 BAT_Tpole_Max_37 "最高电极温度";
CM_ SG_ 2333409125 BAT_Tpole_Min_37 "最低电极温度";
CM_ SG_ 2333409125 BAT_Tpole_Avg_37 "平均电极温度";
CM_ SG_ 2333409125 BAT_Tpole_Max_CSC_37 "最高电极温度所在CSC号";
CM_ SG_ 2333409125 BAT_Tpole_Min_CSC_37 "最低电极温度所在CSC号";
CM_ SG_ 2333409126 CRC_S2A_S14_38 "S2A概要数据14 的CRC";
CM_ SG_ 2333409126 S2A_SUMDATA14_Reserve_38 "预留";
CM_ SG_ 2333409126 BAT_Tpole_Max_38 "最高电极温度";
CM_ SG_ 2333409126 BAT_Tpole_Min_38 "最低电极温度";
CM_ SG_ 2333409126 BAT_Tpole_Avg_38 "平均电极温度";
CM_ SG_ 2333409126 BAT_Tpole_Max_CSC_38 "最高电极温度所在CSC号";
CM_ SG_ 2333409126 BAT_Tpole_Min_CSC_38 "最低电极温度所在CSC号";
CM_ SG_ 2333409127 CRC_S2A_S14_39 "S2A概要数据14 的CRC";
CM_ SG_ 2333409127 S2A_SUMDATA14_Reserve_39 "预留";
CM_ SG_ 2333409127 BAT_Tpole_Max_39 "最高电极温度";
CM_ SG_ 2333409127 BAT_Tpole_Min_39 "最低电极温度";
CM_ SG_ 2333409127 BAT_Tpole_Avg_39 "平均电极温度";
CM_ SG_ 2333409127 BAT_Tpole_Max_CSC_39 "最高电极温度所在CSC号";
CM_ SG_ 2333409127 BAT_Tpole_Min_CSC_39 "最低电极温度所在CSC号";
CM_ SG_ 2333409128 CRC_S2A_S14_40 "S2A概要数据14 的CRC";
CM_ SG_ 2333409128 S2A_SUMDATA14_Reserve_40 "预留";
CM_ SG_ 2333409128 BAT_Tpole_Max_40 "最高电极温度";
CM_ SG_ 2333409128 BAT_Tpole_Min_40 "最低电极温度";
CM_ SG_ 2333409128 BAT_Tpole_Avg_40 "平均电极温度";
CM_ SG_ 2333409128 BAT_Tpole_Max_CSC_40 "最高电极温度所在CSC号";
CM_ SG_ 2333409128 BAT_Tpole_Min_CSC_40 "最低电极温度所在CSC号";
CM_ SG_ 2333409129 CRC_S2A_S14_41 "S2A概要数据14 的CRC";
CM_ SG_ 2333409129 S2A_SUMDATA14_Reserve_41 "预留";
CM_ SG_ 2333409129 BAT_Tpole_Max_41 "最高电极温度";
CM_ SG_ 2333409129 BAT_Tpole_Min_41 "最低电极温度";
CM_ SG_ 2333409129 BAT_Tpole_Avg_41 "平均电极温度";
CM_ SG_ 2333409129 BAT_Tpole_Max_CSC_41 "最高电极温度所在CSC号";
CM_ SG_ 2333409129 BAT_Tpole_Min_CSC_41 "最低电极温度所在CSC号";
CM_ SG_ 2333409130 CRC_S2A_S14_42 "S2A概要数据14 的CRC";
CM_ SG_ 2333409130 S2A_SUMDATA14_Reserve_42 "预留";
CM_ SG_ 2333409130 BAT_Tpole_Max_42 "最高电极温度";
CM_ SG_ 2333409130 BAT_Tpole_Min_42 "最低电极温度";
CM_ SG_ 2333409130 BAT_Tpole_Avg_42 "平均电极温度";
CM_ SG_ 2333409130 BAT_Tpole_Max_CSC_42 "最高电极温度所在CSC号";
CM_ SG_ 2333409130 BAT_Tpole_Min_CSC_42 "最低电极温度所在CSC号";
CM_ SG_ 2333409131 CRC_S2A_S14_43 "S2A概要数据14 的CRC";
CM_ SG_ 2333409131 S2A_SUMDATA14_Reserve_43 "预留";
CM_ SG_ 2333409131 BAT_Tpole_Max_43 "最高电极温度";
CM_ SG_ 2333409131 BAT_Tpole_Min_43 "最低电极温度";
CM_ SG_ 2333409131 BAT_Tpole_Avg_43 "平均电极温度";
CM_ SG_ 2333409131 BAT_Tpole_Max_CSC_43 "最高电极温度所在CSC号";
CM_ SG_ 2333409131 BAT_Tpole_Min_CSC_43 "最低电极温度所在CSC号";
CM_ SG_ 2333409132 CRC_S2A_S14_44 "S2A概要数据14 的CRC";
CM_ SG_ 2333409132 S2A_SUMDATA14_Reserve_44 "预留";
CM_ SG_ 2333409132 BAT_Tpole_Max_44 "最高电极温度";
CM_ SG_ 2333409132 BAT_Tpole_Min_44 "最低电极温度";
CM_ SG_ 2333409132 BAT_Tpole_Avg_44 "平均电极温度";
CM_ SG_ 2333409132 BAT_Tpole_Max_CSC_44 "最高电极温度所在CSC号";
CM_ SG_ 2333409132 BAT_Tpole_Min_CSC_44 "最低电极温度所在CSC号";
CM_ SG_ 2333409133 CRC_S2A_S14_45 "S2A概要数据14 的CRC";
CM_ SG_ 2333409133 S2A_SUMDATA14_Reserve_45 "预留";
CM_ SG_ 2333409133 BAT_Tpole_Max_45 "最高电极温度";
CM_ SG_ 2333409133 BAT_Tpole_Min_45 "最低电极温度";
CM_ SG_ 2333409133 BAT_Tpole_Avg_45 "平均电极温度";
CM_ SG_ 2333409133 BAT_Tpole_Max_CSC_45 "最高电极温度所在CSC号";
CM_ SG_ 2333409133 BAT_Tpole_Min_CSC_45 "最低电极温度所在CSC号";
CM_ SG_ 2333409134 CRC_S2A_S14_46 "S2A概要数据14 的CRC";
CM_ SG_ 2333409134 S2A_SUMDATA14_Reserve_46 "预留";
CM_ SG_ 2333409134 BAT_Tpole_Max_46 "最高电极温度";
CM_ SG_ 2333409134 BAT_Tpole_Min_46 "最低电极温度";
CM_ SG_ 2333409134 BAT_Tpole_Avg_46 "平均电极温度";
CM_ SG_ 2333409134 BAT_Tpole_Max_CSC_46 "最高电极温度所在CSC号";
CM_ SG_ 2333409134 BAT_Tpole_Min_CSC_46 "最低电极温度所在CSC号";
CM_ SG_ 2333409135 CRC_S2A_S14_47 "S2A概要数据14 的CRC";
CM_ SG_ 2333409135 S2A_SUMDATA14_Reserve_47 "预留";
CM_ SG_ 2333409135 BAT_Tpole_Max_47 "最高电极温度";
CM_ SG_ 2333409135 BAT_Tpole_Min_47 "最低电极温度";
CM_ SG_ 2333409135 BAT_Tpole_Avg_47 "平均电极温度";
CM_ SG_ 2333409135 BAT_Tpole_Max_CSC_47 "最高电极温度所在CSC号";
CM_ SG_ 2333409135 BAT_Tpole_Min_CSC_47 "最低电极温度所在CSC号";
CM_ SG_ 2333409136 CRC_S2A_S14_48 "S2A概要数据14 的CRC";
CM_ SG_ 2333409136 S2A_SUMDATA14_Reserve_48 "预留";
CM_ SG_ 2333409136 BAT_Tpole_Max_48 "最高电极温度";
CM_ SG_ 2333409136 BAT_Tpole_Min_48 "最低电极温度";
CM_ SG_ 2333409136 BAT_Tpole_Avg_48 "平均电极温度";
CM_ SG_ 2333409136 BAT_Tpole_Max_CSC_48 "最高电极温度所在CSC号";
CM_ SG_ 2333409136 BAT_Tpole_Min_CSC_48 "最低电极温度所在CSC号";
CM_ SG_ 2333409137 CRC_S2A_S14_49 "S2A概要数据14 的CRC";
CM_ SG_ 2333409137 S2A_SUMDATA14_Reserve_49 "预留";
CM_ SG_ 2333409137 BAT_Tpole_Max_49 "最高电极温度";
CM_ SG_ 2333409137 BAT_Tpole_Min_49 "最低电极温度";
CM_ SG_ 2333409137 BAT_Tpole_Avg_49 "平均电极温度";
CM_ SG_ 2333409137 BAT_Tpole_Max_CSC_49 "最高电极温度所在CSC号";
CM_ SG_ 2333409137 BAT_Tpole_Min_CSC_49 "最低电极温度所在CSC号";
CM_ SG_ 2333409138 CRC_S2A_S14_50 "S2A概要数据14 的CRC";
CM_ SG_ 2333409138 S2A_SUMDATA14_Reserve_50 "预留";
CM_ SG_ 2333409138 BAT_Tpole_Max_50 "最高电极温度";
CM_ SG_ 2333409138 BAT_Tpole_Min_50 "最低电极温度";
CM_ SG_ 2333409138 BAT_Tpole_Avg_50 "平均电极温度";
CM_ SG_ 2333409138 BAT_Tpole_Max_CSC_50 "最高电极温度所在CSC号";
CM_ SG_ 2333409138 BAT_Tpole_Min_CSC_50 "最低电极温度所在CSC号";
CM_ SG_ 2333409139 CRC_S2A_S14_51 "S2A概要数据14 的CRC";
CM_ SG_ 2333409139 S2A_SUMDATA14_Reserve_51 "预留";
CM_ SG_ 2333409139 BAT_Tpole_Max_51 "最高电极温度";
CM_ SG_ 2333409139 BAT_Tpole_Min_51 "最低电极温度";
CM_ SG_ 2333409139 BAT_Tpole_Avg_51 "平均电极温度";
CM_ SG_ 2333409139 BAT_Tpole_Max_CSC_51 "最高电极温度所在CSC号";
CM_ SG_ 2333409139 BAT_Tpole_Min_CSC_51 "最低电极温度所在CSC号";
CM_ SG_ 2333409140 CRC_S2A_S14_52 "S2A概要数据14 的CRC";
CM_ SG_ 2333409140 S2A_SUMDATA14_Reserve_52 "预留";
CM_ SG_ 2333409140 BAT_Tpole_Max_52 "最高电极温度";
CM_ SG_ 2333409140 BAT_Tpole_Min_52 "最低电极温度";
CM_ SG_ 2333409140 BAT_Tpole_Avg_52 "平均电极温度";
CM_ SG_ 2333409140 BAT_Tpole_Max_CSC_52 "最高电极温度所在CSC号";
CM_ SG_ 2333409140 BAT_Tpole_Min_CSC_52 "最低电极温度所在CSC号";
CM_ SG_ 2333409141 CRC_S2A_S14_53 "S2A概要数据14 的CRC";
CM_ SG_ 2333409141 S2A_SUMDATA14_Reserve_53 "预留";
CM_ SG_ 2333409141 BAT_Tpole_Max_53 "最高电极温度";
CM_ SG_ 2333409141 BAT_Tpole_Min_53 "最低电极温度";
CM_ SG_ 2333409141 BAT_Tpole_Avg_53 "平均电极温度";
CM_ SG_ 2333409141 BAT_Tpole_Max_CSC_53 "最高电极温度所在CSC号";
CM_ SG_ 2333409141 BAT_Tpole_Min_CSC_53 "最低电极温度所在CSC号";
CM_ SG_ 2333409142 CRC_S2A_S14_54 "S2A概要数据14 的CRC";
CM_ SG_ 2333409142 S2A_SUMDATA14_Reserve_54 "预留";
CM_ SG_ 2333409142 BAT_Tpole_Max_54 "最高电极温度";
CM_ SG_ 2333409142 BAT_Tpole_Min_54 "最低电极温度";
CM_ SG_ 2333409142 BAT_Tpole_Avg_54 "平均电极温度";
CM_ SG_ 2333409142 BAT_Tpole_Max_CSC_54 "最高电极温度所在CSC号";
CM_ SG_ 2333409142 BAT_Tpole_Min_CSC_54 "最低电极温度所在CSC号";
CM_ SG_ 2333409143 CRC_S2A_S14_55 "S2A概要数据14 的CRC";
CM_ SG_ 2333409143 S2A_SUMDATA14_Reserve_55 "预留";
CM_ SG_ 2333409143 BAT_Tpole_Max_55 "最高电极温度";
CM_ SG_ 2333409143 BAT_Tpole_Min_55 "最低电极温度";
CM_ SG_ 2333409143 BAT_Tpole_Avg_55 "平均电极温度";
CM_ SG_ 2333409143 BAT_Tpole_Max_CSC_55 "最高电极温度所在CSC号";
CM_ SG_ 2333409143 BAT_Tpole_Min_CSC_55 "最低电极温度所在CSC号";
CM_ SG_ 2333409144 CRC_S2A_S14_56 "S2A概要数据14 的CRC";
CM_ SG_ 2333409144 S2A_SUMDATA14_Reserve_56 "预留";
CM_ SG_ 2333409144 BAT_Tpole_Max_56 "最高电极温度";
CM_ SG_ 2333409144 BAT_Tpole_Min_56 "最低电极温度";
CM_ SG_ 2333409144 BAT_Tpole_Avg_56 "平均电极温度";
CM_ SG_ 2333409144 BAT_Tpole_Max_CSC_56 "最高电极温度所在CSC号";
CM_ SG_ 2333409144 BAT_Tpole_Min_CSC_56 "最低电极温度所在CSC号";
CM_ SG_ 2333409145 CRC_S2A_S14_57 "S2A概要数据14 的CRC";
CM_ SG_ 2333409145 S2A_SUMDATA14_Reserve_57 "预留";
CM_ SG_ 2333409145 BAT_Tpole_Max_57 "最高电极温度";
CM_ SG_ 2333409145 BAT_Tpole_Min_57 "最低电极温度";
CM_ SG_ 2333409145 BAT_Tpole_Avg_57 "平均电极温度";
CM_ SG_ 2333409145 BAT_Tpole_Max_CSC_57 "最高电极温度所在CSC号";
CM_ SG_ 2333409145 BAT_Tpole_Min_CSC_57 "最低电极温度所在CSC号";
CM_ SG_ 2333409146 CRC_S2A_S14_58 "S2A概要数据14 的CRC";
CM_ SG_ 2333409146 S2A_SUMDATA14_Reserve_58 "预留";
CM_ SG_ 2333409146 BAT_Tpole_Max_58 "最高电极温度";
CM_ SG_ 2333409146 BAT_Tpole_Min_58 "最低电极温度";
CM_ SG_ 2333409146 BAT_Tpole_Avg_58 "平均电极温度";
CM_ SG_ 2333409146 BAT_Tpole_Max_CSC_58 "最高电极温度所在CSC号";
CM_ SG_ 2333409146 BAT_Tpole_Min_CSC_58 "最低电极温度所在CSC号";
CM_ SG_ 2333409147 CRC_S2A_S14_59 "S2A概要数据14 的CRC";
CM_ SG_ 2333409147 S2A_SUMDATA14_Reserve_59 "预留";
CM_ SG_ 2333409147 BAT_Tpole_Max_59 "最高电极温度";
CM_ SG_ 2333409147 BAT_Tpole_Min_59 "最低电极温度";
CM_ SG_ 2333409147 BAT_Tpole_Avg_59 "平均电极温度";
CM_ SG_ 2333409147 BAT_Tpole_Max_CSC_59 "最高电极温度所在CSC号";
CM_ SG_ 2333409147 BAT_Tpole_Min_CSC_59 "最低电极温度所在CSC号";
CM_ SG_ 2333409148 CRC_S2A_S14_60 "S2A概要数据14 的CRC";
CM_ SG_ 2333409148 S2A_SUMDATA14_Reserve_60 "预留";
CM_ SG_ 2333409148 BAT_Tpole_Max_60 "最高电极温度";
CM_ SG_ 2333409148 BAT_Tpole_Min_60 "最低电极温度";
CM_ SG_ 2333409148 BAT_Tpole_Avg_60 "平均电极温度";
CM_ SG_ 2333409148 BAT_Tpole_Max_CSC_60 "最高电极温度所在CSC号";
CM_ SG_ 2333409148 BAT_Tpole_Min_CSC_60 "最低电极温度所在CSC号";
CM_ SG_ 2333409149 CRC_S2A_S14_61 "S2A概要数据14 的CRC";
CM_ SG_ 2333409149 S2A_SUMDATA14_Reserve_61 "预留";
CM_ SG_ 2333409149 BAT_Tpole_Max_61 "最高电极温度";
CM_ SG_ 2333409149 BAT_Tpole_Min_61 "最低电极温度";
CM_ SG_ 2333409149 BAT_Tpole_Avg_61 "平均电极温度";
CM_ SG_ 2333409149 BAT_Tpole_Max_CSC_61 "最高电极温度所在CSC号";
CM_ SG_ 2333409149 BAT_Tpole_Min_CSC_61 "最低电极温度所在CSC号";
CM_ SG_ 2333409150 CRC_S2A_S14_62 "S2A概要数据14 的CRC";
CM_ SG_ 2333409150 S2A_SUMDATA14_Reserve_62 "预留";
CM_ SG_ 2333409150 BAT_Tpole_Max_62 "最高电极温度";
CM_ SG_ 2333409150 BAT_Tpole_Min_62 "最低电极温度";
CM_ SG_ 2333409150 BAT_Tpole_Avg_62 "平均电极温度";
CM_ SG_ 2333409150 BAT_Tpole_Max_CSC_62 "最高电极温度所在CSC号";
CM_ SG_ 2333409150 BAT_Tpole_Min_CSC_62 "最低电极温度所在CSC号";
CM_ SG_ 2333409151 CRC_S2A_S14_63 "S2A概要数据14 的CRC";
CM_ SG_ 2333409151 S2A_SUMDATA14_Reserve_63 "预留";
CM_ SG_ 2333409151 BAT_Tpole_Max_63 "最高电极温度";
CM_ SG_ 2333409151 BAT_Tpole_Min_63 "最低电极温度";
CM_ SG_ 2333409151 BAT_Tpole_Avg_63 "平均电极温度";
CM_ SG_ 2333409151 BAT_Tpole_Max_CSC_63 "最高电极温度所在CSC号";
CM_ SG_ 2333409151 BAT_Tpole_Min_CSC_63 "最低电极温度所在CSC号";
CM_ SG_ 2333474625 BAT_SysremainEngy_Charge_01 "单柜充电剩余能量";
CM_ SG_ 2333474625 BAT_SysremainEngy_DisCharge_01 "单柜放电剩余能量";
CM_ SG_ 2333474625 BAT_SOE_Charge_01 "单柜可充电SOE";
CM_ SG_ 2333474625 BAT_SOE_DisCharge_01 "单柜可放电SOE";
CM_ SG_ 2333474625 S2A_StepChrMode_01 "Step-Charge模式";
CM_ SG_ 2333474626 BAT_SysremainEngy_Charge_02 "单柜充电剩余能量";
CM_ SG_ 2333474626 BAT_SysremainEngy_DisCharge_02 "单柜放电剩余能量";
CM_ SG_ 2333474626 BAT_SOE_Charge_02 "单柜可充电SOE";
CM_ SG_ 2333474626 BAT_SOE_DisCharge_02 "单柜可放电SOE";
CM_ SG_ 2333474626 S2A_StepChrMode_02 "Step-Charge模式";
CM_ SG_ 2333474627 BAT_SysremainEngy_Charge_03 "单柜充电剩余能量";
CM_ SG_ 2333474627 BAT_SysremainEngy_DisCharge_03 "单柜放电剩余能量";
CM_ SG_ 2333474627 BAT_SOE_Charge_03 "单柜可充电SOE";
CM_ SG_ 2333474627 BAT_SOE_DisCharge_03 "单柜可放电SOE";
CM_ SG_ 2333474627 S2A_StepChrMode_03 "Step-Charge模式";
CM_ SG_ 2333474628 BAT_SysremainEngy_Charge_04 "单柜充电剩余能量";
CM_ SG_ 2333474628 BAT_SysremainEngy_DisCharge_04 "单柜放电剩余能量";
CM_ SG_ 2333474628 BAT_SOE_Charge_04 "单柜可充电SOE";
CM_ SG_ 2333474628 BAT_SOE_DisCharge_04 "单柜可放电SOE";
CM_ SG_ 2333474628 S2A_StepChrMode_04 "Step-Charge模式";
CM_ SG_ 2333474629 BAT_SysremainEngy_Charge_05 "单柜充电剩余能量";
CM_ SG_ 2333474629 BAT_SysremainEngy_DisCharge_05 "单柜放电剩余能量";
CM_ SG_ 2333474629 BAT_SOE_Charge_05 "单柜可充电SOE";
CM_ SG_ 2333474629 BAT_SOE_DisCharge_05 "单柜可放电SOE";
CM_ SG_ 2333474629 S2A_StepChrMode_05 "Step-Charge模式";
CM_ SG_ 2333474630 BAT_SysremainEngy_Charge_06 "单柜充电剩余能量";
CM_ SG_ 2333474630 BAT_SysremainEngy_DisCharge_06 "单柜放电剩余能量";
CM_ SG_ 2333474630 BAT_SOE_Charge_06 "单柜可充电SOE";
CM_ SG_ 2333474630 BAT_SOE_DisCharge_06 "单柜可放电SOE";
CM_ SG_ 2333474630 S2A_StepChrMode_06 "Step-Charge模式";
CM_ SG_ 2333474631 BAT_SysremainEngy_Charge_07 "单柜充电剩余能量";
CM_ SG_ 2333474631 BAT_SysremainEngy_DisCharge_07 "单柜放电剩余能量";
CM_ SG_ 2333474631 BAT_SOE_Charge_07 "单柜可充电SOE";
CM_ SG_ 2333474631 BAT_SOE_DisCharge_07 "单柜可放电SOE";
CM_ SG_ 2333474631 S2A_StepChrMode_07 "Step-Charge模式";
CM_ SG_ 2333474632 BAT_SysremainEngy_Charge_08 "单柜充电剩余能量";
CM_ SG_ 2333474632 BAT_SysremainEngy_DisCharge_08 "单柜放电剩余能量";
CM_ SG_ 2333474632 BAT_SOE_Charge_08 "单柜可充电SOE";
CM_ SG_ 2333474632 BAT_SOE_DisCharge_08 "单柜可放电SOE";
CM_ SG_ 2333474632 S2A_StepChrMode_08 "Step-Charge模式";
CM_ SG_ 2333474633 BAT_SysremainEngy_Charge_09 "单柜充电剩余能量";
CM_ SG_ 2333474633 BAT_SysremainEngy_DisCharge_09 "单柜放电剩余能量";
CM_ SG_ 2333474633 BAT_SOE_Charge_09 "单柜可充电SOE";
CM_ SG_ 2333474633 BAT_SOE_DisCharge_09 "单柜可放电SOE";
CM_ SG_ 2333474633 S2A_StepChrMode_09 "Step-Charge模式";
CM_ SG_ 2333474634 BAT_SysremainEngy_Charge_10 "单柜充电剩余能量";
CM_ SG_ 2333474634 BAT_SysremainEngy_DisCharge_10 "单柜放电剩余能量";
CM_ SG_ 2333474634 BAT_SOE_Charge_10 "单柜可充电SOE";
CM_ SG_ 2333474634 BAT_SOE_DisCharge_10 "单柜可放电SOE";
CM_ SG_ 2333474634 S2A_StepChrMode_10 "Step-Charge模式";
CM_ SG_ 2333474635 BAT_SysremainEngy_Charge_11 "单柜充电剩余能量";
CM_ SG_ 2333474635 BAT_SysremainEngy_DisCharge_11 "单柜放电剩余能量";
CM_ SG_ 2333474635 BAT_SOE_Charge_11 "单柜可充电SOE";
CM_ SG_ 2333474635 BAT_SOE_DisCharge_11 "单柜可放电SOE";
CM_ SG_ 2333474635 S2A_StepChrMode_11 "Step-Charge模式";
CM_ SG_ 2333474636 BAT_SysremainEngy_Charge_12 "单柜充电剩余能量";
CM_ SG_ 2333474636 BAT_SysremainEngy_DisCharge_12 "单柜放电剩余能量";
CM_ SG_ 2333474636 BAT_SOE_Charge_12 "单柜可充电SOE";
CM_ SG_ 2333474636 BAT_SOE_DisCharge_12 "单柜可放电SOE";
CM_ SG_ 2333474636 S2A_StepChrMode_12 "Step-Charge模式";
CM_ SG_ 2333474637 BAT_SysremainEngy_Charge_13 "单柜充电剩余能量";
CM_ SG_ 2333474637 BAT_SysremainEngy_DisCharge_13 "单柜放电剩余能量";
CM_ SG_ 2333474637 BAT_SOE_Charge_13 "单柜可充电SOE";
CM_ SG_ 2333474637 BAT_SOE_DisCharge_13 "单柜可放电SOE";
CM_ SG_ 2333474637 S2A_StepChrMode_13 "Step-Charge模式";
CM_ SG_ 2333474638 BAT_SysremainEngy_Charge_14 "单柜充电剩余能量";
CM_ SG_ 2333474638 BAT_SysremainEngy_DisCharge_14 "单柜放电剩余能量";
CM_ SG_ 2333474638 BAT_SOE_Charge_14 "单柜可充电SOE";
CM_ SG_ 2333474638 BAT_SOE_DisCharge_14 "单柜可放电SOE";
CM_ SG_ 2333474638 S2A_StepChrMode_14 "Step-Charge模式";
CM_ SG_ 2333474639 BAT_SysremainEngy_Charge_15 "单柜充电剩余能量";
CM_ SG_ 2333474639 BAT_SysremainEngy_DisCharge_15 "单柜放电剩余能量";
CM_ SG_ 2333474639 BAT_SOE_Charge_15 "单柜可充电SOE";
CM_ SG_ 2333474639 BAT_SOE_DisCharge_15 "单柜可放电SOE";
CM_ SG_ 2333474639 S2A_StepChrMode_15 "Step-Charge模式";
CM_ SG_ 2333474640 BAT_SysremainEngy_Charge_16 "单柜充电剩余能量";
CM_ SG_ 2333474640 BAT_SysremainEngy_DisCharge_16 "单柜放电剩余能量";
CM_ SG_ 2333474640 BAT_SOE_Charge_16 "单柜可充电SOE";
CM_ SG_ 2333474640 BAT_SOE_DisCharge_16 "单柜可放电SOE";
CM_ SG_ 2333474640 S2A_StepChrMode_16 "Step-Charge模式";
CM_ SG_ 2333474641 BAT_SysremainEngy_Charge_17 "单柜充电剩余能量";
CM_ SG_ 2333474641 BAT_SysremainEngy_DisCharge_17 "单柜放电剩余能量";
CM_ SG_ 2333474641 BAT_SOE_Charge_17 "单柜可充电SOE";
CM_ SG_ 2333474641 BAT_SOE_DisCharge_17 "单柜可放电SOE";
CM_ SG_ 2333474641 S2A_StepChrMode_17 "Step-Charge模式";
CM_ SG_ 2333474642 BAT_SysremainEngy_Charge_18 "单柜充电剩余能量";
CM_ SG_ 2333474642 BAT_SysremainEngy_DisCharge_18 "单柜放电剩余能量";
CM_ SG_ 2333474642 BAT_SOE_Charge_18 "单柜可充电SOE";
CM_ SG_ 2333474642 BAT_SOE_DisCharge_18 "单柜可放电SOE";
CM_ SG_ 2333474642 S2A_StepChrMode_18 "Step-Charge模式";
CM_ SG_ 2333474643 BAT_SysremainEngy_Charge_19 "单柜充电剩余能量";
CM_ SG_ 2333474643 BAT_SysremainEngy_DisCharge_19 "单柜放电剩余能量";
CM_ SG_ 2333474643 BAT_SOE_Charge_19 "单柜可充电SOE";
CM_ SG_ 2333474643 BAT_SOE_DisCharge_19 "单柜可放电SOE";
CM_ SG_ 2333474643 S2A_StepChrMode_19 "Step-Charge模式";
CM_ SG_ 2333474644 BAT_SysremainEngy_Charge_20 "单柜充电剩余能量";
CM_ SG_ 2333474644 BAT_SysremainEngy_DisCharge_20 "单柜放电剩余能量";
CM_ SG_ 2333474644 BAT_SOE_Charge_20 "单柜可充电SOE";
CM_ SG_ 2333474644 BAT_SOE_DisCharge_20 "单柜可放电SOE";
CM_ SG_ 2333474644 S2A_StepChrMode_20 "Step-Charge模式";
CM_ SG_ 2333474645 BAT_SysremainEngy_Charge_21 "单柜充电剩余能量";
CM_ SG_ 2333474645 BAT_SysremainEngy_DisCharge_21 "单柜放电剩余能量";
CM_ SG_ 2333474645 BAT_SOE_Charge_21 "单柜可充电SOE";
CM_ SG_ 2333474645 BAT_SOE_DisCharge_21 "单柜可放电SOE";
CM_ SG_ 2333474645 S2A_StepChrMode_21 "Step-Charge模式";
CM_ SG_ 2333474646 BAT_SysremainEngy_Charge_22 "单柜充电剩余能量";
CM_ SG_ 2333474646 BAT_SysremainEngy_DisCharge_22 "单柜放电剩余能量";
CM_ SG_ 2333474646 BAT_SOE_Charge_22 "单柜可充电SOE";
CM_ SG_ 2333474646 BAT_SOE_DisCharge_22 "单柜可放电SOE";
CM_ SG_ 2333474646 S2A_StepChrMode_22 "Step-Charge模式";
CM_ SG_ 2333474647 BAT_SysremainEngy_Charge_23 "单柜充电剩余能量";
CM_ SG_ 2333474647 BAT_SysremainEngy_DisCharge_23 "单柜放电剩余能量";
CM_ SG_ 2333474647 BAT_SOE_Charge_23 "单柜可充电SOE";
CM_ SG_ 2333474647 BAT_SOE_DisCharge_23 "单柜可放电SOE";
CM_ SG_ 2333474647 S2A_StepChrMode_23 "Step-Charge模式";
CM_ SG_ 2333474648 BAT_SysremainEngy_Charge_24 "单柜充电剩余能量";
CM_ SG_ 2333474648 BAT_SysremainEngy_DisCharge_24 "单柜放电剩余能量";
CM_ SG_ 2333474648 BAT_SOE_Charge_24 "单柜可充电SOE";
CM_ SG_ 2333474648 BAT_SOE_DisCharge_24 "单柜可放电SOE";
CM_ SG_ 2333474648 S2A_StepChrMode_24 "Step-Charge模式";
CM_ SG_ 2333474649 BAT_SysremainEngy_Charge_25 "单柜充电剩余能量";
CM_ SG_ 2333474649 BAT_SysremainEngy_DisCharge_25 "单柜放电剩余能量";
CM_ SG_ 2333474649 BAT_SOE_Charge_25 "单柜可充电SOE";
CM_ SG_ 2333474649 BAT_SOE_DisCharge_25 "单柜可放电SOE";
CM_ SG_ 2333474649 S2A_StepChrMode_25 "Step-Charge模式";
CM_ SG_ 2333474650 BAT_SysremainEngy_Charge_26 "单柜充电剩余能量";
CM_ SG_ 2333474650 BAT_SysremainEngy_DisCharge_26 "单柜放电剩余能量";
CM_ SG_ 2333474650 BAT_SOE_Charge_26 "单柜可充电SOE";
CM_ SG_ 2333474650 BAT_SOE_DisCharge_26 "单柜可放电SOE";
CM_ SG_ 2333474650 S2A_StepChrMode_26 "Step-Charge模式";
CM_ SG_ 2333474651 BAT_SysremainEngy_Charge_27 "单柜充电剩余能量";
CM_ SG_ 2333474651 BAT_SysremainEngy_DisCharge_27 "单柜放电剩余能量";
CM_ SG_ 2333474651 BAT_SOE_Charge_27 "单柜可充电SOE";
CM_ SG_ 2333474651 BAT_SOE_DisCharge_27 "单柜可放电SOE";
CM_ SG_ 2333474651 S2A_StepChrMode_27 "Step-Charge模式";
CM_ SG_ 2333474652 BAT_SysremainEngy_Charge_28 "单柜充电剩余能量";
CM_ SG_ 2333474652 BAT_SysremainEngy_DisCharge_28 "单柜放电剩余能量";
CM_ SG_ 2333474652 BAT_SOE_Charge_28 "单柜可充电SOE";
CM_ SG_ 2333474652 BAT_SOE_DisCharge_28 "单柜可放电SOE";
CM_ SG_ 2333474652 S2A_StepChrMode_28 "Step-Charge模式";
CM_ SG_ 2333474653 BAT_SysremainEngy_Charge_29 "单柜充电剩余能量";
CM_ SG_ 2333474653 BAT_SysremainEngy_DisCharge_29 "单柜放电剩余能量";
CM_ SG_ 2333474653 BAT_SOE_Charge_29 "单柜可充电SOE";
CM_ SG_ 2333474653 BAT_SOE_DisCharge_29 "单柜可放电SOE";
CM_ SG_ 2333474653 S2A_StepChrMode_29 "Step-Charge模式";
CM_ SG_ 2333474654 BAT_SysremainEngy_Charge_30 "单柜充电剩余能量";
CM_ SG_ 2333474654 BAT_SysremainEngy_DisCharge_30 "单柜放电剩余能量";
CM_ SG_ 2333474654 BAT_SOE_Charge_30 "单柜可充电SOE";
CM_ SG_ 2333474654 BAT_SOE_DisCharge_30 "单柜可放电SOE";
CM_ SG_ 2333474654 S2A_StepChrMode_30 "Step-Charge模式";
CM_ SG_ 2333474655 BAT_SysremainEngy_Charge_31 "单柜充电剩余能量";
CM_ SG_ 2333474655 BAT_SysremainEngy_DisCharge_31 "单柜放电剩余能量";
CM_ SG_ 2333474655 BAT_SOE_Charge_31 "单柜可充电SOE";
CM_ SG_ 2333474655 BAT_SOE_DisCharge_31 "单柜可放电SOE";
CM_ SG_ 2333474655 S2A_StepChrMode_31 "Step-Charge模式";
CM_ SG_ 2333474656 BAT_SysremainEngy_Charge_32 "单柜充电剩余能量";
CM_ SG_ 2333474656 BAT_SysremainEngy_DisCharge_32 "单柜放电剩余能量";
CM_ SG_ 2333474656 BAT_SOE_Charge_32 "单柜可充电SOE";
CM_ SG_ 2333474656 BAT_SOE_DisCharge_32 "单柜可放电SOE";
CM_ SG_ 2333474656 S2A_StepChrMode_32 "Step-Charge模式";
CM_ SG_ 2333474657 BAT_SysremainEngy_Charge_33 "单柜充电剩余能量";
CM_ SG_ 2333474657 BAT_SysremainEngy_DisCharge_33 "单柜放电剩余能量";
CM_ SG_ 2333474657 BAT_SOE_Charge_33 "单柜可充电SOE";
CM_ SG_ 2333474657 BAT_SOE_DisCharge_33 "单柜可放电SOE";
CM_ SG_ 2333474657 S2A_StepChrMode_33 "Step-Charge模式";
CM_ SG_ 2333474658 BAT_SysremainEngy_Charge_34 "单柜充电剩余能量";
CM_ SG_ 2333474658 BAT_SysremainEngy_DisCharge_34 "单柜放电剩余能量";
CM_ SG_ 2333474658 BAT_SOE_Charge_34 "单柜可充电SOE";
CM_ SG_ 2333474658 BAT_SOE_DisCharge_34 "单柜可放电SOE";
CM_ SG_ 2333474658 S2A_StepChrMode_34 "Step-Charge模式";
CM_ SG_ 2333474659 BAT_SysremainEngy_Charge_35 "单柜充电剩余能量";
CM_ SG_ 2333474659 BAT_SysremainEngy_DisCharge_35 "单柜放电剩余能量";
CM_ SG_ 2333474659 BAT_SOE_Charge_35 "单柜可充电SOE";
CM_ SG_ 2333474659 BAT_SOE_DisCharge_35 "单柜可放电SOE";
CM_ SG_ 2333474659 S2A_StepChrMode_35 "Step-Charge模式";
CM_ SG_ 2333474660 BAT_SysremainEngy_Charge_36 "单柜充电剩余能量";
CM_ SG_ 2333474660 BAT_SysremainEngy_DisCharge_36 "单柜放电剩余能量";
CM_ SG_ 2333474660 BAT_SOE_Charge_36 "单柜可充电SOE";
CM_ SG_ 2333474660 BAT_SOE_DisCharge_36 "单柜可放电SOE";
CM_ SG_ 2333474660 S2A_StepChrMode_36 "Step-Charge模式";
CM_ SG_ 2333474661 BAT_SysremainEngy_Charge_37 "单柜充电剩余能量";
CM_ SG_ 2333474661 BAT_SysremainEngy_DisCharge_37 "单柜放电剩余能量";
CM_ SG_ 2333474661 BAT_SOE_Charge_37 "单柜可充电SOE";
CM_ SG_ 2333474661 BAT_SOE_DisCharge_37 "单柜可放电SOE";
CM_ SG_ 2333474661 S2A_StepChrMode_37 "Step-Charge模式";
CM_ SG_ 2333474662 BAT_SysremainEngy_Charge_38 "单柜充电剩余能量";
CM_ SG_ 2333474662 BAT_SysremainEngy_DisCharge_38 "单柜放电剩余能量";
CM_ SG_ 2333474662 BAT_SOE_Charge_38 "单柜可充电SOE";
CM_ SG_ 2333474662 BAT_SOE_DisCharge_38 "单柜可放电SOE";
CM_ SG_ 2333474662 S2A_StepChrMode_38 "Step-Charge模式";
CM_ SG_ 2333474663 BAT_SysremainEngy_Charge_39 "单柜充电剩余能量";
CM_ SG_ 2333474663 BAT_SysremainEngy_DisCharge_39 "单柜放电剩余能量";
CM_ SG_ 2333474663 BAT_SOE_Charge_39 "单柜可充电SOE";
CM_ SG_ 2333474663 BAT_SOE_DisCharge_39 "单柜可放电SOE";
CM_ SG_ 2333474663 S2A_StepChrMode_39 "Step-Charge模式";
CM_ SG_ 2333474664 BAT_SysremainEngy_Charge_40 "单柜充电剩余能量";
CM_ SG_ 2333474664 BAT_SysremainEngy_DisCharge_40 "单柜放电剩余能量";
CM_ SG_ 2333474664 BAT_SOE_Charge_40 "单柜可充电SOE";
CM_ SG_ 2333474664 BAT_SOE_DisCharge_40 "单柜可放电SOE";
CM_ SG_ 2333474664 S2A_StepChrMode_40 "Step-Charge模式";
CM_ SG_ 2333474665 BAT_SysremainEngy_Charge_41 "单柜充电剩余能量";
CM_ SG_ 2333474665 BAT_SysremainEngy_DisCharge_41 "单柜放电剩余能量";
CM_ SG_ 2333474665 BAT_SOE_Charge_41 "单柜可充电SOE";
CM_ SG_ 2333474665 BAT_SOE_DisCharge_41 "单柜可放电SOE";
CM_ SG_ 2333474665 S2A_StepChrMode_41 "Step-Charge模式";
CM_ SG_ 2333474666 BAT_SysremainEngy_Charge_42 "单柜充电剩余能量";
CM_ SG_ 2333474666 BAT_SysremainEngy_DisCharge_42 "单柜放电剩余能量";
CM_ SG_ 2333474666 BAT_SOE_Charge_42 "单柜可充电SOE";
CM_ SG_ 2333474666 BAT_SOE_DisCharge_42 "单柜可放电SOE";
CM_ SG_ 2333474666 S2A_StepChrMode_42 "Step-Charge模式";
CM_ SG_ 2333474667 BAT_SysremainEngy_Charge_43 "单柜充电剩余能量";
CM_ SG_ 2333474667 BAT_SysremainEngy_DisCharge_43 "单柜放电剩余能量";
CM_ SG_ 2333474667 BAT_SOE_Charge_43 "单柜可充电SOE";
CM_ SG_ 2333474667 BAT_SOE_DisCharge_43 "单柜可放电SOE";
CM_ SG_ 2333474667 S2A_StepChrMode_43 "Step-Charge模式";
CM_ SG_ 2333474668 BAT_SysremainEngy_Charge_44 "单柜充电剩余能量";
CM_ SG_ 2333474668 BAT_SysremainEngy_DisCharge_44 "单柜放电剩余能量";
CM_ SG_ 2333474668 BAT_SOE_Charge_44 "单柜可充电SOE";
CM_ SG_ 2333474668 BAT_SOE_DisCharge_44 "单柜可放电SOE";
CM_ SG_ 2333474668 S2A_StepChrMode_44 "Step-Charge模式";
CM_ SG_ 2333474669 BAT_SysremainEngy_Charge_45 "单柜充电剩余能量";
CM_ SG_ 2333474669 BAT_SysremainEngy_DisCharge_45 "单柜放电剩余能量";
CM_ SG_ 2333474669 BAT_SOE_Charge_45 "单柜可充电SOE";
CM_ SG_ 2333474669 BAT_SOE_DisCharge_45 "单柜可放电SOE";
CM_ SG_ 2333474669 S2A_StepChrMode_45 "Step-Charge模式";
CM_ SG_ 2333474670 BAT_SysremainEngy_Charge_46 "单柜充电剩余能量";
CM_ SG_ 2333474670 BAT_SysremainEngy_DisCharge_46 "单柜放电剩余能量";
CM_ SG_ 2333474670 BAT_SOE_Charge_46 "单柜可充电SOE";
CM_ SG_ 2333474670 BAT_SOE_DisCharge_46 "单柜可放电SOE";
CM_ SG_ 2333474670 S2A_StepChrMode_46 "Step-Charge模式";
CM_ SG_ 2333474671 BAT_SysremainEngy_Charge_47 "单柜充电剩余能量";
CM_ SG_ 2333474671 BAT_SysremainEngy_DisCharge_47 "单柜放电剩余能量";
CM_ SG_ 2333474671 BAT_SOE_Charge_47 "单柜可充电SOE";
CM_ SG_ 2333474671 BAT_SOE_DisCharge_47 "单柜可放电SOE";
CM_ SG_ 2333474671 S2A_StepChrMode_47 "Step-Charge模式";
CM_ SG_ 2333474672 BAT_SysremainEngy_Charge_48 "单柜充电剩余能量";
CM_ SG_ 2333474672 BAT_SysremainEngy_DisCharge_48 "单柜放电剩余能量";
CM_ SG_ 2333474672 BAT_SOE_Charge_48 "单柜可充电SOE";
CM_ SG_ 2333474672 BAT_SOE_DisCharge_48 "单柜可放电SOE";
CM_ SG_ 2333474672 S2A_StepChrMode_48 "Step-Charge模式";
CM_ SG_ 2333474673 BAT_SysremainEngy_Charge_49 "单柜充电剩余能量";
CM_ SG_ 2333474673 BAT_SysremainEngy_DisCharge_49 "单柜放电剩余能量";
CM_ SG_ 2333474673 BAT_SOE_Charge_49 "单柜可充电SOE";
CM_ SG_ 2333474673 BAT_SOE_DisCharge_49 "单柜可放电SOE";
CM_ SG_ 2333474673 S2A_StepChrMode_49 "Step-Charge模式";
CM_ SG_ 2333474674 BAT_SysremainEngy_Charge_50 "单柜充电剩余能量";
CM_ SG_ 2333474674 BAT_SysremainEngy_DisCharge_50 "单柜放电剩余能量";
CM_ SG_ 2333474674 BAT_SOE_Charge_50 "单柜可充电SOE";
CM_ SG_ 2333474674 BAT_SOE_DisCharge_50 "单柜可放电SOE";
CM_ SG_ 2333474674 S2A_StepChrMode_50 "Step-Charge模式";
CM_ SG_ 2333474675 BAT_SysremainEngy_Charge_51 "单柜充电剩余能量";
CM_ SG_ 2333474675 BAT_SysremainEngy_DisCharge_51 "单柜放电剩余能量";
CM_ SG_ 2333474675 BAT_SOE_Charge_51 "单柜可充电SOE";
CM_ SG_ 2333474675 BAT_SOE_DisCharge_51 "单柜可放电SOE";
CM_ SG_ 2333474675 S2A_StepChrMode_51 "Step-Charge模式";
CM_ SG_ 2333474676 BAT_SysremainEngy_Charge_52 "单柜充电剩余能量";
CM_ SG_ 2333474676 BAT_SysremainEngy_DisCharge_52 "单柜放电剩余能量";
CM_ SG_ 2333474676 BAT_SOE_Charge_52 "单柜可充电SOE";
CM_ SG_ 2333474676 BAT_SOE_DisCharge_52 "单柜可放电SOE";
CM_ SG_ 2333474676 S2A_StepChrMode_52 "Step-Charge模式";
CM_ SG_ 2333474677 BAT_SysremainEngy_Charge_53 "单柜充电剩余能量";
CM_ SG_ 2333474677 BAT_SysremainEngy_DisCharge_53 "单柜放电剩余能量";
CM_ SG_ 2333474677 BAT_SOE_Charge_53 "单柜可充电SOE";
CM_ SG_ 2333474677 BAT_SOE_DisCharge_53 "单柜可放电SOE";
CM_ SG_ 2333474677 S2A_StepChrMode_53 "Step-Charge模式";
CM_ SG_ 2333474678 BAT_SysremainEngy_Charge_54 "单柜充电剩余能量";
CM_ SG_ 2333474678 BAT_SysremainEngy_DisCharge_54 "单柜放电剩余能量";
CM_ SG_ 2333474678 BAT_SOE_Charge_54 "单柜可充电SOE";
CM_ SG_ 2333474678 BAT_SOE_DisCharge_54 "单柜可放电SOE";
CM_ SG_ 2333474678 S2A_StepChrMode_54 "Step-Charge模式";
CM_ SG_ 2333474679 BAT_SysremainEngy_Charge_55 "单柜充电剩余能量";
CM_ SG_ 2333474679 BAT_SysremainEngy_DisCharge_55 "单柜放电剩余能量";
CM_ SG_ 2333474679 BAT_SOE_Charge_55 "单柜可充电SOE";
CM_ SG_ 2333474679 BAT_SOE_DisCharge_55 "单柜可放电SOE";
CM_ SG_ 2333474679 S2A_StepChrMode_55 "Step-Charge模式";
CM_ SG_ 2333474680 BAT_SysremainEngy_Charge_56 "单柜充电剩余能量";
CM_ SG_ 2333474680 BAT_SysremainEngy_DisCharge_56 "单柜放电剩余能量";
CM_ SG_ 2333474680 BAT_SOE_Charge_56 "单柜可充电SOE";
CM_ SG_ 2333474680 BAT_SOE_DisCharge_56 "单柜可放电SOE";
CM_ SG_ 2333474680 S2A_StepChrMode_56 "Step-Charge模式";
CM_ SG_ 2333474681 BAT_SysremainEngy_Charge_57 "单柜充电剩余能量";
CM_ SG_ 2333474681 BAT_SysremainEngy_DisCharge_57 "单柜放电剩余能量";
CM_ SG_ 2333474681 BAT_SOE_Charge_57 "单柜可充电SOE";
CM_ SG_ 2333474681 BAT_SOE_DisCharge_57 "单柜可放电SOE";
CM_ SG_ 2333474681 S2A_StepChrMode_57 "Step-Charge模式";
CM_ SG_ 2333474682 BAT_SysremainEngy_Charge_58 "单柜充电剩余能量";
CM_ SG_ 2333474682 BAT_SysremainEngy_DisCharge_58 "单柜放电剩余能量";
CM_ SG_ 2333474682 BAT_SOE_Charge_58 "单柜可充电SOE";
CM_ SG_ 2333474682 BAT_SOE_DisCharge_58 "单柜可放电SOE";
CM_ SG_ 2333474682 S2A_StepChrMode_58 "Step-Charge模式";
CM_ SG_ 2333474683 BAT_SysremainEngy_Charge_59 "单柜充电剩余能量";
CM_ SG_ 2333474683 BAT_SysremainEngy_DisCharge_59 "单柜放电剩余能量";
CM_ SG_ 2333474683 BAT_SOE_Charge_59 "单柜可充电SOE";
CM_ SG_ 2333474683 BAT_SOE_DisCharge_59 "单柜可放电SOE";
CM_ SG_ 2333474683 S2A_StepChrMode_59 "Step-Charge模式";
CM_ SG_ 2333474684 BAT_SysremainEngy_Charge_60 "单柜充电剩余能量";
CM_ SG_ 2333474684 BAT_SysremainEngy_DisCharge_60 "单柜放电剩余能量";
CM_ SG_ 2333474684 BAT_SOE_Charge_60 "单柜可充电SOE";
CM_ SG_ 2333474684 BAT_SOE_DisCharge_60 "单柜可放电SOE";
CM_ SG_ 2333474684 S2A_StepChrMode_60 "Step-Charge模式";
CM_ SG_ 2333474685 BAT_SysremainEngy_Charge_61 "单柜充电剩余能量";
CM_ SG_ 2333474685 BAT_SysremainEngy_DisCharge_61 "单柜放电剩余能量";
CM_ SG_ 2333474685 BAT_SOE_Charge_61 "单柜可充电SOE";
CM_ SG_ 2333474685 BAT_SOE_DisCharge_61 "单柜可放电SOE";
CM_ SG_ 2333474685 S2A_StepChrMode_61 "Step-Charge模式";
CM_ SG_ 2333474686 BAT_SysremainEngy_Charge_62 "单柜充电剩余能量";
CM_ SG_ 2333474686 BAT_SysremainEngy_DisCharge_62 "单柜放电剩余能量";
CM_ SG_ 2333474686 BAT_SOE_Charge_62 "单柜可充电SOE";
CM_ SG_ 2333474686 BAT_SOE_DisCharge_62 "单柜可放电SOE";
CM_ SG_ 2333474686 S2A_StepChrMode_62 "Step-Charge模式";
CM_ SG_ 2333474687 BAT_SysremainEngy_Charge_63 "单柜充电剩余能量";
CM_ SG_ 2333474687 BAT_SysremainEngy_DisCharge_63 "单柜放电剩余能量";
CM_ SG_ 2333474687 BAT_SOE_Charge_63 "单柜可充电SOE";
CM_ SG_ 2333474687 BAT_SOE_DisCharge_63 "单柜可放电SOE";
CM_ SG_ 2333474687 S2A_StepChrMode_63 "Step-Charge模式";
CM_ SG_ 2333540161 BAT_Lmt_ChCurrent_01 "单柜最大允许充电电流";
CM_ SG_ 2333540161 BAT_Lmt_DisChCurrent_01 "单柜最大允许放电电流";
CM_ SG_ 2333540161 BAT_Lmt_ChPwr_01 "单柜最大允许充电功率";
CM_ SG_ 2333540161 BAT_Lmt_DisChPwr_01 "单柜最大允许放电功率";
CM_ SG_ 2333540162 BAT_Lmt_ChCurrent_02 "单柜最大允许充电电流";
CM_ SG_ 2333540162 BAT_Lmt_DisChCurrent_02 "单柜最大允许放电电流";
CM_ SG_ 2333540162 BAT_Lmt_ChPwr_02 "单柜最大允许充电功率";
CM_ SG_ 2333540162 BAT_Lmt_DisChPwr_02 "单柜最大允许放电功率";
CM_ SG_ 2333540163 BAT_Lmt_ChCurrent_03 "单柜最大允许充电电流";
CM_ SG_ 2333540163 BAT_Lmt_DisChCurrent_03 "单柜最大允许放电电流";
CM_ SG_ 2333540163 BAT_Lmt_ChPwr_03 "单柜最大允许充电功率";
CM_ SG_ 2333540163 BAT_Lmt_DisChPwr_03 "单柜最大允许放电功率";
CM_ SG_ 2333540164 BAT_Lmt_ChCurrent_04 "单柜最大允许充电电流";
CM_ SG_ 2333540164 BAT_Lmt_DisChCurrent_04 "单柜最大允许放电电流";
CM_ SG_ 2333540164 BAT_Lmt_ChPwr_04 "单柜最大允许充电功率";
CM_ SG_ 2333540164 BAT_Lmt_DisChPwr_04 "单柜最大允许放电功率";
CM_ SG_ 2333540165 BAT_Lmt_ChCurrent_05 "单柜最大允许充电电流";
CM_ SG_ 2333540165 BAT_Lmt_DisChCurrent_05 "单柜最大允许放电电流";
CM_ SG_ 2333540165 BAT_Lmt_ChPwr_05 "单柜最大允许充电功率";
CM_ SG_ 2333540165 BAT_Lmt_DisChPwr_05 "单柜最大允许放电功率";
CM_ SG_ 2333540166 BAT_Lmt_ChCurrent_06 "单柜最大允许充电电流";
CM_ SG_ 2333540166 BAT_Lmt_DisChCurrent_06 "单柜最大允许放电电流";
CM_ SG_ 2333540166 BAT_Lmt_ChPwr_06 "单柜最大允许充电功率";
CM_ SG_ 2333540166 BAT_Lmt_DisChPwr_06 "单柜最大允许放电功率";
CM_ SG_ 2333540167 BAT_Lmt_ChCurrent_07 "单柜最大允许充电电流";
CM_ SG_ 2333540167 BAT_Lmt_DisChCurrent_07 "单柜最大允许放电电流";
CM_ SG_ 2333540167 BAT_Lmt_ChPwr_07 "单柜最大允许充电功率";
CM_ SG_ 2333540167 BAT_Lmt_DisChPwr_07 "单柜最大允许放电功率";
CM_ SG_ 2333540168 BAT_Lmt_ChCurrent_08 "单柜最大允许充电电流";
CM_ SG_ 2333540168 BAT_Lmt_DisChCurrent_08 "单柜最大允许放电电流";
CM_ SG_ 2333540168 BAT_Lmt_ChPwr_08 "单柜最大允许充电功率";
CM_ SG_ 2333540168 BAT_Lmt_DisChPwr_08 "单柜最大允许放电功率";
CM_ SG_ 2333540169 BAT_Lmt_ChCurrent_09 "单柜最大允许充电电流";
CM_ SG_ 2333540169 BAT_Lmt_DisChCurrent_09 "单柜最大允许放电电流";
CM_ SG_ 2333540169 BAT_Lmt_ChPwr_09 "单柜最大允许充电功率";
CM_ SG_ 2333540169 BAT_Lmt_DisChPwr_09 "单柜最大允许放电功率";
CM_ SG_ 2333540170 BAT_Lmt_ChCurrent_10 "单柜最大允许充电电流";
CM_ SG_ 2333540170 BAT_Lmt_DisChCurrent_10 "单柜最大允许放电电流";
CM_ SG_ 2333540170 BAT_Lmt_ChPwr_10 "单柜最大允许充电功率";
CM_ SG_ 2333540170 BAT_Lmt_DisChPwr_10 "单柜最大允许放电功率";
CM_ SG_ 2333540171 BAT_Lmt_ChCurrent_11 "单柜最大允许充电电流";
CM_ SG_ 2333540171 BAT_Lmt_DisChCurrent_11 "单柜最大允许放电电流";
CM_ SG_ 2333540171 BAT_Lmt_ChPwr_11 "单柜最大允许充电功率";
CM_ SG_ 2333540171 BAT_Lmt_DisChPwr_11 "单柜最大允许放电功率";
CM_ SG_ 2333540172 BAT_Lmt_ChCurrent_12 "单柜最大允许充电电流";
CM_ SG_ 2333540172 BAT_Lmt_DisChCurrent_12 "单柜最大允许放电电流";
CM_ SG_ 2333540172 BAT_Lmt_ChPwr_12 "单柜最大允许充电功率";
CM_ SG_ 2333540172 BAT_Lmt_DisChPwr_12 "单柜最大允许放电功率";
CM_ SG_ 2333540173 BAT_Lmt_ChCurrent_13 "单柜最大允许充电电流";
CM_ SG_ 2333540173 BAT_Lmt_DisChCurrent_13 "单柜最大允许放电电流";
CM_ SG_ 2333540173 BAT_Lmt_ChPwr_13 "单柜最大允许充电功率";
CM_ SG_ 2333540173 BAT_Lmt_DisChPwr_13 "单柜最大允许放电功率";
CM_ SG_ 2333540174 BAT_Lmt_ChCurrent_14 "单柜最大允许充电电流";
CM_ SG_ 2333540174 BAT_Lmt_DisChCurrent_14 "单柜最大允许放电电流";
CM_ SG_ 2333540174 BAT_Lmt_ChPwr_14 "单柜最大允许充电功率";
CM_ SG_ 2333540174 BAT_Lmt_DisChPwr_14 "单柜最大允许放电功率";
CM_ SG_ 2333540175 BAT_Lmt_ChCurrent_15 "单柜最大允许充电电流";
CM_ SG_ 2333540175 BAT_Lmt_DisChCurrent_15 "单柜最大允许放电电流";
CM_ SG_ 2333540175 BAT_Lmt_ChPwr_15 "单柜最大允许充电功率";
CM_ SG_ 2333540175 BAT_Lmt_DisChPwr_15 "单柜最大允许放电功率";
CM_ SG_ 2333540176 BAT_Lmt_ChCurrent_16 "单柜最大允许充电电流";
CM_ SG_ 2333540176 BAT_Lmt_DisChCurrent_16 "单柜最大允许放电电流";
CM_ SG_ 2333540176 BAT_Lmt_ChPwr_16 "单柜最大允许充电功率";
CM_ SG_ 2333540176 BAT_Lmt_DisChPwr_16 "单柜最大允许放电功率";
CM_ SG_ 2333540177 BAT_Lmt_ChCurrent_17 "单柜最大允许充电电流";
CM_ SG_ 2333540177 BAT_Lmt_DisChCurrent_17 "单柜最大允许放电电流";
CM_ SG_ 2333540177 BAT_Lmt_ChPwr_17 "单柜最大允许充电功率";
CM_ SG_ 2333540177 BAT_Lmt_DisChPwr_17 "单柜最大允许放电功率";
CM_ SG_ 2333540178 BAT_Lmt_ChCurrent_18 "单柜最大允许充电电流";
CM_ SG_ 2333540178 BAT_Lmt_DisChCurrent_18 "单柜最大允许放电电流";
CM_ SG_ 2333540178 BAT_Lmt_ChPwr_18 "单柜最大允许充电功率";
CM_ SG_ 2333540178 BAT_Lmt_DisChPwr_18 "单柜最大允许放电功率";
CM_ SG_ 2333540179 BAT_Lmt_ChCurrent_19 "单柜最大允许充电电流";
CM_ SG_ 2333540179 BAT_Lmt_DisChCurrent_19 "单柜最大允许放电电流";
CM_ SG_ 2333540179 BAT_Lmt_ChPwr_19 "单柜最大允许充电功率";
CM_ SG_ 2333540179 BAT_Lmt_DisChPwr_19 "单柜最大允许放电功率";
CM_ SG_ 2333540180 BAT_Lmt_ChCurrent_20 "单柜最大允许充电电流";
CM_ SG_ 2333540180 BAT_Lmt_DisChCurrent_20 "单柜最大允许放电电流";
CM_ SG_ 2333540180 BAT_Lmt_ChPwr_20 "单柜最大允许充电功率";
CM_ SG_ 2333540180 BAT_Lmt_DisChPwr_20 "单柜最大允许放电功率";
CM_ SG_ 2333540181 BAT_Lmt_ChCurrent_21 "单柜最大允许充电电流";
CM_ SG_ 2333540181 BAT_Lmt_DisChCurrent_21 "单柜最大允许放电电流";
CM_ SG_ 2333540181 BAT_Lmt_ChPwr_21 "单柜最大允许充电功率";
CM_ SG_ 2333540181 BAT_Lmt_DisChPwr_21 "单柜最大允许放电功率";
CM_ SG_ 2333540182 BAT_Lmt_ChCurrent_22 "单柜最大允许充电电流";
CM_ SG_ 2333540182 BAT_Lmt_DisChCurrent_22 "单柜最大允许放电电流";
CM_ SG_ 2333540182 BAT_Lmt_ChPwr_22 "单柜最大允许充电功率";
CM_ SG_ 2333540182 BAT_Lmt_DisChPwr_22 "单柜最大允许放电功率";
CM_ SG_ 2333540183 BAT_Lmt_ChCurrent_23 "单柜最大允许充电电流";
CM_ SG_ 2333540183 BAT_Lmt_DisChCurrent_23 "单柜最大允许放电电流";
CM_ SG_ 2333540183 BAT_Lmt_ChPwr_23 "单柜最大允许充电功率";
CM_ SG_ 2333540183 BAT_Lmt_DisChPwr_23 "单柜最大允许放电功率";
CM_ SG_ 2333540184 BAT_Lmt_ChCurrent_24 "单柜最大允许充电电流";
CM_ SG_ 2333540184 BAT_Lmt_DisChCurrent_24 "单柜最大允许放电电流";
CM_ SG_ 2333540184 BAT_Lmt_ChPwr_24 "单柜最大允许充电功率";
CM_ SG_ 2333540184 BAT_Lmt_DisChPwr_24 "单柜最大允许放电功率";
CM_ SG_ 2333540185 BAT_Lmt_ChCurrent_25 "单柜最大允许充电电流";
CM_ SG_ 2333540185 BAT_Lmt_DisChCurrent_25 "单柜最大允许放电电流";
CM_ SG_ 2333540185 BAT_Lmt_ChPwr_25 "单柜最大允许充电功率";
CM_ SG_ 2333540185 BAT_Lmt_DisChPwr_25 "单柜最大允许放电功率";
CM_ SG_ 2333540186 BAT_Lmt_ChCurrent_26 "单柜最大允许充电电流";
CM_ SG_ 2333540186 BAT_Lmt_DisChCurrent_26 "单柜最大允许放电电流";
CM_ SG_ 2333540186 BAT_Lmt_ChPwr_26 "单柜最大允许充电功率";
CM_ SG_ 2333540186 BAT_Lmt_DisChPwr_26 "单柜最大允许放电功率";
CM_ SG_ 2333540187 BAT_Lmt_ChCurrent_27 "单柜最大允许充电电流";
CM_ SG_ 2333540187 BAT_Lmt_DisChCurrent_27 "单柜最大允许放电电流";
CM_ SG_ 2333540187 BAT_Lmt_ChPwr_27 "单柜最大允许充电功率";
CM_ SG_ 2333540187 BAT_Lmt_DisChPwr_27 "单柜最大允许放电功率";
CM_ SG_ 2333540188 BAT_Lmt_ChCurrent_28 "单柜最大允许充电电流";
CM_ SG_ 2333540188 BAT_Lmt_DisChCurrent_28 "单柜最大允许放电电流";
CM_ SG_ 2333540188 BAT_Lmt_ChPwr_28 "单柜最大允许充电功率";
CM_ SG_ 2333540188 BAT_Lmt_DisChPwr_28 "单柜最大允许放电功率";
CM_ SG_ 2333540189 BAT_Lmt_ChCurrent_29 "单柜最大允许充电电流";
CM_ SG_ 2333540189 BAT_Lmt_DisChCurrent_29 "单柜最大允许放电电流";
CM_ SG_ 2333540189 BAT_Lmt_ChPwr_29 "单柜最大允许充电功率";
CM_ SG_ 2333540189 BAT_Lmt_DisChPwr_29 "单柜最大允许放电功率";
CM_ SG_ 2333540190 BAT_Lmt_ChCurrent_30 "单柜最大允许充电电流";
CM_ SG_ 2333540190 BAT_Lmt_DisChCurrent_30 "单柜最大允许放电电流";
CM_ SG_ 2333540190 BAT_Lmt_ChPwr_30 "单柜最大允许充电功率";
CM_ SG_ 2333540190 BAT_Lmt_DisChPwr_30 "单柜最大允许放电功率";
CM_ SG_ 2333540191 BAT_Lmt_ChCurrent_31 "单柜最大允许充电电流";
CM_ SG_ 2333540191 BAT_Lmt_DisChCurrent_31 "单柜最大允许放电电流";
CM_ SG_ 2333540191 BAT_Lmt_ChPwr_31 "单柜最大允许充电功率";
CM_ SG_ 2333540191 BAT_Lmt_DisChPwr_31 "单柜最大允许放电功率";
CM_ SG_ 2333540192 BAT_Lmt_ChCurrent_32 "单柜最大允许充电电流";
CM_ SG_ 2333540192 BAT_Lmt_DisChCurrent_32 "单柜最大允许放电电流";
CM_ SG_ 2333540192 BAT_Lmt_ChPwr_32 "单柜最大允许充电功率";
CM_ SG_ 2333540192 BAT_Lmt_DisChPwr_32 "单柜最大允许放电功率";
CM_ SG_ 2333540193 BAT_Lmt_ChCurrent_33 "单柜最大允许充电电流";
CM_ SG_ 2333540193 BAT_Lmt_DisChCurrent_33 "单柜最大允许放电电流";
CM_ SG_ 2333540193 BAT_Lmt_ChPwr_33 "单柜最大允许充电功率";
CM_ SG_ 2333540193 BAT_Lmt_DisChPwr_33 "单柜最大允许放电功率";
CM_ SG_ 2333540194 BAT_Lmt_ChCurrent_34 "单柜最大允许充电电流";
CM_ SG_ 2333540194 BAT_Lmt_DisChCurrent_34 "单柜最大允许放电电流";
CM_ SG_ 2333540194 BAT_Lmt_ChPwr_34 "单柜最大允许充电功率";
CM_ SG_ 2333540194 BAT_Lmt_DisChPwr_34 "单柜最大允许放电功率";
CM_ SG_ 2333540195 BAT_Lmt_ChCurrent_35 "单柜最大允许充电电流";
CM_ SG_ 2333540195 BAT_Lmt_DisChCurrent_35 "单柜最大允许放电电流";
CM_ SG_ 2333540195 BAT_Lmt_ChPwr_35 "单柜最大允许充电功率";
CM_ SG_ 2333540195 BAT_Lmt_DisChPwr_35 "单柜最大允许放电功率";
CM_ SG_ 2333540196 BAT_Lmt_ChCurrent_36 "单柜最大允许充电电流";
CM_ SG_ 2333540196 BAT_Lmt_DisChCurrent_36 "单柜最大允许放电电流";
CM_ SG_ 2333540196 BAT_Lmt_ChPwr_36 "单柜最大允许充电功率";
CM_ SG_ 2333540196 BAT_Lmt_DisChPwr_36 "单柜最大允许放电功率";
CM_ SG_ 2333540197 BAT_Lmt_ChCurrent_37 "单柜最大允许充电电流";
CM_ SG_ 2333540197 BAT_Lmt_DisChCurrent_37 "单柜最大允许放电电流";
CM_ SG_ 2333540197 BAT_Lmt_ChPwr_37 "单柜最大允许充电功率";
CM_ SG_ 2333540197 BAT_Lmt_DisChPwr_37 "单柜最大允许放电功率";
CM_ SG_ 2333540198 BAT_Lmt_ChCurrent_38 "单柜最大允许充电电流";
CM_ SG_ 2333540198 BAT_Lmt_DisChCurrent_38 "单柜最大允许放电电流";
CM_ SG_ 2333540198 BAT_Lmt_ChPwr_38 "单柜最大允许充电功率";
CM_ SG_ 2333540198 BAT_Lmt_DisChPwr_38 "单柜最大允许放电功率";
CM_ SG_ 2333540199 BAT_Lmt_ChCurrent_39 "单柜最大允许充电电流";
CM_ SG_ 2333540199 BAT_Lmt_DisChCurrent_39 "单柜最大允许放电电流";
CM_ SG_ 2333540199 BAT_Lmt_ChPwr_39 "单柜最大允许充电功率";
CM_ SG_ 2333540199 BAT_Lmt_DisChPwr_39 "单柜最大允许放电功率";
CM_ SG_ 2333540200 BAT_Lmt_ChCurrent_40 "单柜最大允许充电电流";
CM_ SG_ 2333540200 BAT_Lmt_DisChCurrent_40 "单柜最大允许放电电流";
CM_ SG_ 2333540200 BAT_Lmt_ChPwr_40 "单柜最大允许充电功率";
CM_ SG_ 2333540200 BAT_Lmt_DisChPwr_40 "单柜最大允许放电功率";
CM_ SG_ 2333540201 BAT_Lmt_ChCurrent_41 "单柜最大允许充电电流";
CM_ SG_ 2333540201 BAT_Lmt_DisChCurrent_41 "单柜最大允许放电电流";
CM_ SG_ 2333540201 BAT_Lmt_ChPwr_41 "单柜最大允许充电功率";
CM_ SG_ 2333540201 BAT_Lmt_DisChPwr_41 "单柜最大允许放电功率";
CM_ SG_ 2333540202 BAT_Lmt_ChCurrent_42 "单柜最大允许充电电流";
CM_ SG_ 2333540202 BAT_Lmt_DisChCurrent_42 "单柜最大允许放电电流";
CM_ SG_ 2333540202 BAT_Lmt_ChPwr_42 "单柜最大允许充电功率";
CM_ SG_ 2333540202 BAT_Lmt_DisChPwr_42 "单柜最大允许放电功率";
CM_ SG_ 2333540203 BAT_Lmt_ChCurrent_43 "单柜最大允许充电电流";
CM_ SG_ 2333540203 BAT_Lmt_DisChCurrent_43 "单柜最大允许放电电流";
CM_ SG_ 2333540203 BAT_Lmt_ChPwr_43 "单柜最大允许充电功率";
CM_ SG_ 2333540203 BAT_Lmt_DisChPwr_43 "单柜最大允许放电功率";
CM_ SG_ 2333540204 BAT_Lmt_ChCurrent_44 "单柜最大允许充电电流";
CM_ SG_ 2333540204 BAT_Lmt_DisChCurrent_44 "单柜最大允许放电电流";
CM_ SG_ 2333540204 BAT_Lmt_ChPwr_44 "单柜最大允许充电功率";
CM_ SG_ 2333540204 BAT_Lmt_DisChPwr_44 "单柜最大允许放电功率";
CM_ SG_ 2333540205 BAT_Lmt_ChCurrent_45 "单柜最大允许充电电流";
CM_ SG_ 2333540205 BAT_Lmt_DisChCurrent_45 "单柜最大允许放电电流";
CM_ SG_ 2333540205 BAT_Lmt_ChPwr_45 "单柜最大允许充电功率";
CM_ SG_ 2333540205 BAT_Lmt_DisChPwr_45 "单柜最大允许放电功率";
CM_ SG_ 2333540206 BAT_Lmt_ChCurrent_46 "单柜最大允许充电电流";
CM_ SG_ 2333540206 BAT_Lmt_DisChCurrent_46 "单柜最大允许放电电流";
CM_ SG_ 2333540206 BAT_Lmt_ChPwr_46 "单柜最大允许充电功率";
CM_ SG_ 2333540206 BAT_Lmt_DisChPwr_46 "单柜最大允许放电功率";
CM_ SG_ 2333540207 BAT_Lmt_ChCurrent_47 "单柜最大允许充电电流";
CM_ SG_ 2333540207 BAT_Lmt_DisChCurrent_47 "单柜最大允许放电电流";
CM_ SG_ 2333540207 BAT_Lmt_ChPwr_47 "单柜最大允许充电功率";
CM_ SG_ 2333540207 BAT_Lmt_DisChPwr_47 "单柜最大允许放电功率";
CM_ SG_ 2333540208 BAT_Lmt_ChCurrent_48 "单柜最大允许充电电流";
CM_ SG_ 2333540208 BAT_Lmt_DisChCurrent_48 "单柜最大允许放电电流";
CM_ SG_ 2333540208 BAT_Lmt_ChPwr_48 "单柜最大允许充电功率";
CM_ SG_ 2333540208 BAT_Lmt_DisChPwr_48 "单柜最大允许放电功率";
CM_ SG_ 2333540209 BAT_Lmt_ChCurrent_49 "单柜最大允许充电电流";
CM_ SG_ 2333540209 BAT_Lmt_DisChCurrent_49 "单柜最大允许放电电流";
CM_ SG_ 2333540209 BAT_Lmt_ChPwr_49 "单柜最大允许充电功率";
CM_ SG_ 2333540209 BAT_Lmt_DisChPwr_49 "单柜最大允许放电功率";
CM_ SG_ 2333540210 BAT_Lmt_ChCurrent_50 "单柜最大允许充电电流";
CM_ SG_ 2333540210 BAT_Lmt_DisChCurrent_50 "单柜最大允许放电电流";
CM_ SG_ 2333540210 BAT_Lmt_ChPwr_50 "单柜最大允许充电功率";
CM_ SG_ 2333540210 BAT_Lmt_DisChPwr_50 "单柜最大允许放电功率";
CM_ SG_ 2333540211 BAT_Lmt_ChCurrent_51 "单柜最大允许充电电流";
CM_ SG_ 2333540211 BAT_Lmt_DisChCurrent_51 "单柜最大允许放电电流";
CM_ SG_ 2333540211 BAT_Lmt_ChPwr_51 "单柜最大允许充电功率";
CM_ SG_ 2333540211 BAT_Lmt_DisChPwr_51 "单柜最大允许放电功率";
CM_ SG_ 2333540212 BAT_Lmt_ChCurrent_52 "单柜最大允许充电电流";
CM_ SG_ 2333540212 BAT_Lmt_DisChCurrent_52 "单柜最大允许放电电流";
CM_ SG_ 2333540212 BAT_Lmt_ChPwr_52 "单柜最大允许充电功率";
CM_ SG_ 2333540212 BAT_Lmt_DisChPwr_52 "单柜最大允许放电功率";
CM_ SG_ 2333540213 BAT_Lmt_ChCurrent_53 "单柜最大允许充电电流";
CM_ SG_ 2333540213 BAT_Lmt_DisChCurrent_53 "单柜最大允许放电电流";
CM_ SG_ 2333540213 BAT_Lmt_ChPwr_53 "单柜最大允许充电功率";
CM_ SG_ 2333540213 BAT_Lmt_DisChPwr_53 "单柜最大允许放电功率";
CM_ SG_ 2333540214 BAT_Lmt_ChCurrent_54 "单柜最大允许充电电流";
CM_ SG_ 2333540214 BAT_Lmt_DisChCurrent_54 "单柜最大允许放电电流";
CM_ SG_ 2333540214 BAT_Lmt_ChPwr_54 "单柜最大允许充电功率";
CM_ SG_ 2333540214 BAT_Lmt_DisChPwr_54 "单柜最大允许放电功率";
CM_ SG_ 2333540215 BAT_Lmt_ChCurrent_55 "单柜最大允许充电电流";
CM_ SG_ 2333540215 BAT_Lmt_DisChCurrent_55 "单柜最大允许放电电流";
CM_ SG_ 2333540215 BAT_Lmt_ChPwr_55 "单柜最大允许充电功率";
CM_ SG_ 2333540215 BAT_Lmt_DisChPwr_55 "单柜最大允许放电功率";
CM_ SG_ 2333540216 BAT_Lmt_ChCurrent_56 "单柜最大允许充电电流";
CM_ SG_ 2333540216 BAT_Lmt_DisChCurrent_56 "单柜最大允许放电电流";
CM_ SG_ 2333540216 BAT_Lmt_ChPwr_56 "单柜最大允许充电功率";
CM_ SG_ 2333540216 BAT_Lmt_DisChPwr_56 "单柜最大允许放电功率";
CM_ SG_ 2333540217 BAT_Lmt_ChCurrent_57 "单柜最大允许充电电流";
CM_ SG_ 2333540217 BAT_Lmt_DisChCurrent_57 "单柜最大允许放电电流";
CM_ SG_ 2333540217 BAT_Lmt_ChPwr_57 "单柜最大允许充电功率";
CM_ SG_ 2333540217 BAT_Lmt_DisChPwr_57 "单柜最大允许放电功率";
CM_ SG_ 2333540218 BAT_Lmt_ChCurrent_58 "单柜最大允许充电电流";
CM_ SG_ 2333540218 BAT_Lmt_DisChCurrent_58 "单柜最大允许放电电流";
CM_ SG_ 2333540218 BAT_Lmt_ChPwr_58 "单柜最大允许充电功率";
CM_ SG_ 2333540218 BAT_Lmt_DisChPwr_58 "单柜最大允许放电功率";
CM_ SG_ 2333540219 BAT_Lmt_ChCurrent_59 "单柜最大允许充电电流";
CM_ SG_ 2333540219 BAT_Lmt_DisChCurrent_59 "单柜最大允许放电电流";
CM_ SG_ 2333540219 BAT_Lmt_ChPwr_59 "单柜最大允许充电功率";
CM_ SG_ 2333540219 BAT_Lmt_DisChPwr_59 "单柜最大允许放电功率";
CM_ SG_ 2333540220 BAT_Lmt_ChCurrent_60 "单柜最大允许充电电流";
CM_ SG_ 2333540220 BAT_Lmt_DisChCurrent_60 "单柜最大允许放电电流";
CM_ SG_ 2333540220 BAT_Lmt_ChPwr_60 "单柜最大允许充电功率";
CM_ SG_ 2333540220 BAT_Lmt_DisChPwr_60 "单柜最大允许放电功率";
CM_ SG_ 2333540221 BAT_Lmt_ChCurrent_61 "单柜最大允许充电电流";
CM_ SG_ 2333540221 BAT_Lmt_DisChCurrent_61 "单柜最大允许放电电流";
CM_ SG_ 2333540221 BAT_Lmt_ChPwr_61 "单柜最大允许充电功率";
CM_ SG_ 2333540221 BAT_Lmt_DisChPwr_61 "单柜最大允许放电功率";
CM_ SG_ 2333540222 BAT_Lmt_ChCurrent_62 "单柜最大允许充电电流";
CM_ SG_ 2333540222 BAT_Lmt_DisChCurrent_62 "单柜最大允许放电电流";
CM_ SG_ 2333540222 BAT_Lmt_ChPwr_62 "单柜最大允许充电功率";
CM_ SG_ 2333540222 BAT_Lmt_DisChPwr_62 "单柜最大允许放电功率";
CM_ SG_ 2333540223 BAT_Lmt_ChCurrent_63 "单柜最大允许充电电流";
CM_ SG_ 2333540223 BAT_Lmt_DisChCurrent_63 "单柜最大允许放电电流";
CM_ SG_ 2333540223 BAT_Lmt_ChPwr_63 "单柜最大允许充电功率";
CM_ SG_ 2333540223 BAT_Lmt_DisChPwr_63 "单柜最大允许放电功率";
CM_ SG_ 2333605697 S2A_HisOVtimes_01 "极限过压故障累积次数";
CM_ SG_ 2333605697 S2A_HisUVtimes_01 "极限欠压故障累积次数";
CM_ SG_ 2333605697 S2A_HisOCCtimes_01 "充电过流4级故障累积次数";
CM_ SG_ 2333605697 S2A_HisOCDtimes_01 "放电过流4级故障累积次数";
CM_ SG_ 2333605698 S2A_HisOVtimes_02 "极限过压故障累积次数";
CM_ SG_ 2333605698 S2A_HisUVtimes_02 "极限欠压故障累积次数";
CM_ SG_ 2333605698 S2A_HisOCCtimes_02 "充电过流4级故障累积次数";
CM_ SG_ 2333605698 S2A_HisOCDtimes_02 "放电过流4级故障累积次数";
CM_ SG_ 2333605699 S2A_HisOVtimes_03 "极限过压故障累积次数";
CM_ SG_ 2333605699 S2A_HisUVtimes_03 "极限欠压故障累积次数";
CM_ SG_ 2333605699 S2A_HisOCCtimes_03 "充电过流4级故障累积次数";
CM_ SG_ 2333605699 S2A_HisOCDtimes_03 "放电过流4级故障累积次数";
CM_ SG_ 2333605700 S2A_HisOVtimes_04 "极限过压故障累积次数";
CM_ SG_ 2333605700 S2A_HisUVtimes_04 "极限欠压故障累积次数";
CM_ SG_ 2333605700 S2A_HisOCCtimes_04 "充电过流4级故障累积次数";
CM_ SG_ 2333605700 S2A_HisOCDtimes_04 "放电过流4级故障累积次数";
CM_ SG_ 2333605701 S2A_HisOVtimes_05 "极限过压故障累积次数";
CM_ SG_ 2333605701 S2A_HisUVtimes_05 "极限欠压故障累积次数";
CM_ SG_ 2333605701 S2A_HisOCCtimes_05 "充电过流4级故障累积次数";
CM_ SG_ 2333605701 S2A_HisOCDtimes_05 "放电过流4级故障累积次数";
CM_ SG_ 2333605702 S2A_HisOVtimes_06 "极限过压故障累积次数";
CM_ SG_ 2333605702 S2A_HisUVtimes_06 "极限欠压故障累积次数";
CM_ SG_ 2333605702 S2A_HisOCCtimes_06 "充电过流4级故障累积次数";
CM_ SG_ 2333605702 S2A_HisOCDtimes_06 "放电过流4级故障累积次数";
CM_ SG_ 2333605703 S2A_HisOVtimes_07 "极限过压故障累积次数";
CM_ SG_ 2333605703 S2A_HisUVtimes_07 "极限欠压故障累积次数";
CM_ SG_ 2333605703 S2A_HisOCCtimes_07 "充电过流4级故障累积次数";
CM_ SG_ 2333605703 S2A_HisOCDtimes_07 "放电过流4级故障累积次数";
CM_ SG_ 2333605704 S2A_HisOVtimes_08 "极限过压故障累积次数";
CM_ SG_ 2333605704 S2A_HisUVtimes_08 "极限欠压故障累积次数";
CM_ SG_ 2333605704 S2A_HisOCCtimes_08 "充电过流4级故障累积次数";
CM_ SG_ 2333605704 S2A_HisOCDtimes_08 "放电过流4级故障累积次数";
CM_ SG_ 2333605705 S2A_HisOVtimes_09 "极限过压故障累积次数";
CM_ SG_ 2333605705 S2A_HisUVtimes_09 "极限欠压故障累积次数";
CM_ SG_ 2333605705 S2A_HisOCCtimes_09 "充电过流4级故障累积次数";
CM_ SG_ 2333605705 S2A_HisOCDtimes_09 "放电过流4级故障累积次数";
CM_ SG_ 2333605706 S2A_HisOVtimes_10 "极限过压故障累积次数";
CM_ SG_ 2333605706 S2A_HisUVtimes_10 "极限欠压故障累积次数";
CM_ SG_ 2333605706 S2A_HisOCCtimes_10 "充电过流4级故障累积次数";
CM_ SG_ 2333605706 S2A_HisOCDtimes_10 "放电过流4级故障累积次数";
CM_ SG_ 2333605707 S2A_HisOVtimes_11 "极限过压故障累积次数";
CM_ SG_ 2333605707 S2A_HisUVtimes_11 "极限欠压故障累积次数";
CM_ SG_ 2333605707 S2A_HisOCCtimes_11 "充电过流4级故障累积次数";
CM_ SG_ 2333605707 S2A_HisOCDtimes_11 "放电过流4级故障累积次数";
CM_ SG_ 2333605708 S2A_HisOVtimes_12 "极限过压故障累积次数";
CM_ SG_ 2333605708 S2A_HisUVtimes_12 "极限欠压故障累积次数";
CM_ SG_ 2333605708 S2A_HisOCCtimes_12 "充电过流4级故障累积次数";
CM_ SG_ 2333605708 S2A_HisOCDtimes_12 "放电过流4级故障累积次数";
CM_ SG_ 2333605709 S2A_HisOVtimes_13 "极限过压故障累积次数";
CM_ SG_ 2333605709 S2A_HisUVtimes_13 "极限欠压故障累积次数";
CM_ SG_ 2333605709 S2A_HisOCCtimes_13 "充电过流4级故障累积次数";
CM_ SG_ 2333605709 S2A_HisOCDtimes_13 "放电过流4级故障累积次数";
CM_ SG_ 2333605710 S2A_HisOVtimes_14 "极限过压故障累积次数";
CM_ SG_ 2333605710 S2A_HisUVtimes_14 "极限欠压故障累积次数";
CM_ SG_ 2333605710 S2A_HisOCCtimes_14 "充电过流4级故障累积次数";
CM_ SG_ 2333605710 S2A_HisOCDtimes_14 "放电过流4级故障累积次数";
CM_ SG_ 2333605711 S2A_HisOVtimes_15 "极限过压故障累积次数";
CM_ SG_ 2333605711 S2A_HisUVtimes_15 "极限欠压故障累积次数";
CM_ SG_ 2333605711 S2A_HisOCCtimes_15 "充电过流4级故障累积次数";
CM_ SG_ 2333605711 S2A_HisOCDtimes_15 "放电过流4级故障累积次数";
CM_ SG_ 2333605712 S2A_HisOVtimes_16 "极限过压故障累积次数";
CM_ SG_ 2333605712 S2A_HisUVtimes_16 "极限欠压故障累积次数";
CM_ SG_ 2333605712 S2A_HisOCCtimes_16 "充电过流4级故障累积次数";
CM_ SG_ 2333605712 S2A_HisOCDtimes_16 "放电过流4级故障累积次数";
CM_ SG_ 2333605713 S2A_HisOVtimes_17 "极限过压故障累积次数";
CM_ SG_ 2333605713 S2A_HisUVtimes_17 "极限欠压故障累积次数";
CM_ SG_ 2333605713 S2A_HisOCCtimes_17 "充电过流4级故障累积次数";
CM_ SG_ 2333605713 S2A_HisOCDtimes_17 "放电过流4级故障累积次数";
VAL_ 2333343589 S2A_TRDM_ThrmlRnwyFltCseMsk_37 1 "bit0:欠压和过温" 2 "bit1:欠压和温升速率过大" 4 "bit2:欠压和温差过大" 8 "bit3:温升速率过大和过温" 16 "bit4:温升速率过大和温差过大" 32 "bit5:采样线掉线和过温" 64 "bit6:采样线掉线和温升速率过大" 128 "bit7采样线掉线和温差过大" ;
VAL_ 2333343589 S2A_TRDM_ThrmlRnwyFltCSC_37 1 "CSC1#" 2 "CSC2#" 3 "CSC3#" 4 "CSC4#" 5 "CSC5#" 6 "CSC6#" 7 "CSC7#" 8 "CSC8#" ;
VAL_ 2333343590 S2A_TRDM_ThrmlRnwyFltCseMsk_38 1 "bit0:欠压和过温" 2 "bit1:欠压和温升速率过大" 4 "bit2:欠压和温差过大" 8 "bit3:温升速率过大和过温" 16 "bit4:温升速率过大和温差过大" 32 "bit5:采样线掉线和过温" 64 "bit6:采样线掉线和温升速率过大" 128 "bit7采样线掉线和温差过大" ;
VAL_ 2333343590 S2A_TRDM_ThrmlRnwyFltCSC_38 1 "CSC1#" 2 "CSC2#" 3 "CSC3#" 4 "CSC4#" 5 "CSC5#" 6 "CSC6#" 7 "CSC7#" 8 "CSC8#" ;
VAL_ 2333343591 S2A_TRDM_ThrmlRnwyFltCseMsk_39 1 "bit0:欠压和过温" 2 "bit1:欠压和温升速率过大" 4 "bit2:欠压和温差过大" 8 "bit3:温升速率过大和过温" 16 "bit4:温升速率过大和温差过大" 32 "bit5:采样线掉线和过温" 64 "bit6:采样线掉线和温升速率过大" 128 "bit7采样线掉线和温差过大" ;
VAL_ 2333343591 S2A_TRDM_ThrmlRnwyFltCSC_39 1 "CSC1#" 2 "CSC2#" 3 "CSC3#" 4 "CSC4#" 5 "CSC5#" 6 "CSC6#" 7 "CSC7#" 8 "CSC8#" ;
VAL_ 2333343592 S2A_TRDM_ThrmlRnwyFltCseMsk_40 1 "bit0:欠压和过温" 2 "bit1:欠压和温升速率过大" 4 "bit2:欠压和温差过大" 8 "bit3:温升速率过大和过温" 16 "bit4:温升速率过大和温差过大" 32 "bit5:采样线掉线和过温" 64 "bit6:采样线掉线和温升速率过大" 128 "bit7采样线掉线和温差过大" ;
VAL_ 2333343592 S2A_TRDM_ThrmlRnwyFltCSC_40 1 "CSC1#" 2 "CSC2#" 3 "CSC3#" 4 "CSC4#" 5 "CSC5#" 6 "CSC6#" 7 "CSC7#" 8 "CSC8#" ;
VAL_ 2333343593 S2A_TRDM_ThrmlRnwyFltCseMsk_41 1 "bit0:欠压和过温" 2 "bit1:欠压和温升速率过大" 4 "bit2:欠压和温差过大" 8 "bit3:温升速率过大和过温" 16 "bit4:温升速率过大和温差过大" 32 "bit5:采样线掉线和过温" 64 "bit6:采样线掉线和温升速率过大" 128 "bit7采样线掉线和温差过大" ;
VAL_ 2333343593 S2A_TRDM_ThrmlRnwyFltCSC_41 1 "CSC1#" 2 "CSC2#" 3 "CSC3#" 4 "CSC4#" 5 "CSC5#" 6 "CSC6#" 7 "CSC7#" 8 "CSC8#" ;
VAL_ 2333343594 S2A_TRDM_ThrmlRnwyFltCseMsk_42 1 "bit0:欠压和过温" 2 "bit1:欠压和温升速率过大" 4 "bit2:欠压和温差过大" 8 "bit3:温升速率过大和过温" 16 "bit4:温升速率过大和温差过大" 32 "bit5:采样线掉线和过温" 64 "bit6:采样线掉线和温升速率过大" 128 "bit7采样线掉线和温差过大" ;
VAL_ 2333343594 S2A_TRDM_ThrmlRnwyFltCSC_42 1 "CSC1#" 2 "CSC2#" 3 "CSC3#" 4 "CSC4#" 5 "CSC5#" 6 "CSC6#" 7 "CSC7#" 8 "CSC8#" ;
VAL_ 2333343595 S2A_TRDM_ThrmlRnwyFltCseMsk_43 1 "bit0:欠压和过温" 2 "bit1:欠压和温升速率过大" 4 "bit2:欠压和温差过大" 8 "bit3:温升速率过大和过温" 16 "bit4:温升速率过大和温差过大" 32 "bit5:采样线掉线和过温" 64 "bit6:采样线掉线和温升速率过大" 128 "bit7采样线掉线和温差过大" ;
VAL_ 2333343595 S2A_TRDM_ThrmlRnwyFltCSC_43 1 "CSC1#" 2 "CSC2#" 3 "CSC3#" 4 "CSC4#" 5 "CSC5#" 6 "CSC6#" 7 "CSC7#" 8 "CSC8#" ;
VAL_ 2333343596 S2A_TRDM_ThrmlRnwyFltCseMsk_44 1 "bit0:欠压和过温" 2 "bit1:欠压和温升速率过大" 4 "bit2:欠压和温差过大" 8 "bit3:温升速率过大和过温" 16 "bit4:温升速率过大和温差过大" 32 "bit5:采样线掉线和过温" 64 "bit6:采样线掉线和温升速率过大" 128 "bit7采样线掉线和温差过大" ;
VAL_ 2333343596 S2A_TRDM_ThrmlRnwyFltCSC_44 1 "CSC1#" 2 "CSC2#" 3 "CSC3#" 4 "CSC4#" 5 "CSC5#" 6 "CSC6#" 7 "CSC7#" 8 "CSC8#" ;
VAL_ 2333343597 S2A_TRDM_ThrmlRnwyFltCseMsk_45 1 "bit0:欠压和过温" 2 "bit1:欠压和温升速率过大" 4 "bit2:欠压和温差过大" 8 "bit3:温升速率过大和过温" 16 "bit4:温升速率过大和温差过大" 32 "bit5:采样线掉线和过温" 64 "bit6:采样线掉线和温升速率过大" 128 "bit7采样线掉线和温差过大" ;
VAL_ 2333343597 S2A_TRDM_ThrmlRnwyFltCSC_45 1 "CSC1#" 2 "CSC2#" 3 "CSC3#" 4 "CSC4#" 5 "CSC5#" 6 "CSC6#" 7 "CSC7#" 8 "CSC8#" ;
VAL_ 2333343598 S2A_TRDM_ThrmlRnwyFltCseMsk_46 1 "bit0:欠压和过温" 2 "bit1:欠压和温升速率过大" 4 "bit2:欠压和温差过大" 8 "bit3:温升速率过大和过温" 16 "bit4:温升速率过大和温差过大" 32 "bit5:采样线掉线和过温" 64 "bit6:采样线掉线和温升速率过大" 128 "bit7采样线掉线和温差过大" ;
VAL_ 2333343598 S2A_TRDM_ThrmlRnwyFltCSC_46 1 "CSC1#" 2 "CSC2#" 3 "CSC3#" 4 "CSC4#" 5 "CSC5#" 6 "CSC6#" 7 "CSC7#" 8 "CSC8#" ;
VAL_ 2333343599 S2A_TRDM_ThrmlRnwyFltCseMsk_47 1 "bit0:欠压和过温" 2 "bit1:欠压和温升速率过大" 4 "bit2:欠压和温差过大" 8 "bit3:温升速率过大和过温" 16 "bit4:温升速率过大和温差过大" 32 "bit5:采样线掉线和过温" 64 "bit6:采样线掉线和温升速率过大" 128 "bit7采样线掉线和温差过大" ;
VAL_ 2333343599 S2A_TRDM_ThrmlRnwyFltCSC_47 1 "CSC1#" 2 "CSC2#" 3 "CSC3#" 4 "CSC4#" 5 "CSC5#" 6 "CSC6#" 7 "CSC7#" 8 "CSC8#" ;
VAL_ 2333343600 S2A_TRDM_ThrmlRnwyFltCseMsk_48 1 "bit0:欠压和过温" 2 "bit1:欠压和温升速率过大" 4 "bit2:欠压和温差过大" 8 "bit3:温升速率过大和过温" 16 "bit4:温升速率过大和温差过大" 32 "bit5:采样线掉线和过温" 64 "bit6:采样线掉线和温升速率过大" 128 "bit7采样线掉线和温差过大" ;
VAL_ 2333343600 S2A_TRDM_ThrmlRnwyFltCSC_48 1 "CSC1#" 2 "CSC2#" 3 "CSC3#" 4 "CSC4#" 5 "CSC5#" 6 "CSC6#" 7 "CSC7#" 8 "CSC8#" ;
VAL_ 2333343601 S2A_TRDM_ThrmlRnwyFltCseMsk_49 1 "bit0:欠压和过温" 2 "bit1:欠压和温升速率过大" 4 "bit2:欠压和温差过大" 8 "bit3:温升速率过大和过温" 16 "bit4:温升速率过大和温差过大" 32 "bit5:采样线掉线和过温" 64 "bit6:采样线掉线和温升速率过大" 128 "bit7采样线掉线和温差过大" ;
VAL_ 2333343601 S2A_TRDM_ThrmlRnwyFltCSC_49 1 "CSC1#" 2 "CSC2#" 3 "CSC3#" 4 "CSC4#" 5 "CSC5#" 6 "CSC6#" 7 "CSC7#" 8 "CSC8#" ;
VAL_ 2333343602 S2A_TRDM_ThrmlRnwyFltCseMsk_50 1 "bit0:欠压和过温" 2 "bit1:欠压和温升速率过大" 4 "bit2:欠压和温差过大" 8 "bit3:温升速率过大和过温" 16 "bit4:温升速率过大和温差过大" 32 "bit5:采样线掉线和过温" 64 "bit6:采样线掉线和温升速率过大" 128 "bit7采样线掉线和温差过大" ;
VAL_ 2333343602 S2A_TRDM_ThrmlRnwyFltCSC_50 1 "CSC1#" 2 "CSC2#" 3 "CSC3#" 4 "CSC4#" 5 "CSC5#" 6 "CSC6#" 7 "CSC7#" 8 "CSC8#" ;
VAL_ 2333343603 S2A_TRDM_ThrmlRnwyFltCseMsk_51 1 "bit0:欠压和过温" 2 "bit1:欠压和温升速率过大" 4 "bit2:欠压和温差过大" 8 "bit3:温升速率过大和过温" 16 "bit4:温升速率过大和温差过大" 32 "bit5:采样线掉线和过温" 64 "bit6:采样线掉线和温升速率过大" 128 "bit7采样线掉线和温差过大" ;
VAL_ 2333343603 S2A_TRDM_ThrmlRnwyFltCSC_51 1 "CSC1#" 2 "CSC2#" 3 "CSC3#" 4 "CSC4#" 5 "CSC5#" 6 "CSC6#" 7 "CSC7#" 8 "CSC8#" ;
VAL_ 2333343604 S2A_TRDM_ThrmlRnwyFltCseMsk_52 1 "bit0:欠压和过温" 2 "bit1:欠压和温升速率过大" 4 "bit2:欠压和温差过大" 8 "bit3:温升速率过大和过温" 16 "bit4:温升速率过大和温差过大" 32 "bit5:采样线掉线和过温" 64 "bit6:采样线掉线和温升速率过大" 128 "bit7采样线掉线和温差过大" ;
VAL_ 2333343604 S2A_TRDM_ThrmlRnwyFltCSC_52 1 "CSC1#" 2 "CSC2#" 3 "CSC3#" 4 "CSC4#" 5 "CSC5#" 6 "CSC6#" 7 "CSC7#" 8 "CSC8#" ;
VAL_ 2333343605 S2A_TRDM_ThrmlRnwyFltCseMsk_53 1 "bit0:欠压和过温" 2 "bit1:欠压和温升速率过大" 4 "bit2:欠压和温差过大" 8 "bit3:温升速率过大和过温" 16 "bit4:温升速率过大和温差过大" 32 "bit5:采样线掉线和过温" 64 "bit6:采样线掉线和温升速率过大" 128 "bit7采样线掉线和温差过大" ;
VAL_ 2333343605 S2A_TRDM_ThrmlRnwyFltCSC_53 1 "CSC1#" 2 "CSC2#" 3 "CSC3#" 4 "CSC4#" 5 "CSC5#" 6 "CSC6#" 7 "CSC7#" 8 "CSC8#" ;
VAL_ 2333343606 S2A_TRDM_ThrmlRnwyFltCseMsk_54 1 "bit0:欠压和过温" 2 "bit1:欠压和温升速率过大" 4 "bit2:欠压和温差过大" 8 "bit3:温升速率过大和过温" 16 "bit4:温升速率过大和温差过大" 32 "bit5:采样线掉线和过温" 64 "bit6:采样线掉线和温升速率过大" 128 "bit7采样线掉线和温差过大" ;
VAL_ 2333343606 S2A_TRDM_ThrmlRnwyFltCSC_54 1 "CSC1#" 2 "CSC2#" 3 "CSC3#" 4 "CSC4#" 5 "CSC5#" 6 "CSC6#" 7 "CSC7#" 8 "CSC8#" ;
VAL_ 2333343607 S2A_TRDM_ThrmlRnwyFltCseMsk_55 1 "bit0:欠压和过温" 2 "bit1:欠压和温升速率过大" 4 "bit2:欠压和温差过大" 8 "bit3:温升速率过大和过温" 16 "bit4:温升速率过大和温差过大" 32 "bit5:采样线掉线和过温" 64 "bit6:采样线掉线和温升速率过大" 128 "bit7采样线掉线和温差过大" ;
VAL_ 2333343607 S2A_TRDM_ThrmlRnwyFltCSC_55 1 "CSC1#" 2 "CSC2#" 3 "CSC3#" 4 "CSC4#" 5 "CSC5#" 6 "CSC6#" 7 "CSC7#" 8 "CSC8#" ;
VAL_ 2333343608 S2A_TRDM_ThrmlRnwyFltCseMsk_56 1 "bit0:欠压和过温" 2 "bit1:欠压和温升速率过大" 4 "bit2:欠压和温差过大" 8 "bit3:温升速率过大和过温" 16 "bit4:温升速率过大和温差过大" 32 "bit5:采样线掉线和过温" 64 "bit6:采样线掉线和温升速率过大" 128 "bit7采样线掉线和温差过大" ;
VAL_ 2333343608 S2A_TRDM_ThrmlRnwyFltCSC_56 1 "CSC1#" 2 "CSC2#" 3 "CSC3#" 4 "CSC4#" 5 "CSC5#" 6 "CSC6#" 7 "CSC7#" 8 "CSC8#" ;
VAL_ 2333343609 S2A_TRDM_ThrmlRnwyFltCseMsk_57 1 "bit0:欠压和过温" 2 "bit1:欠压和温升速率过大" 4 "bit2:欠压和温差过大" 8 "bit3:温升速率过大和过温" 16 "bit4:温升速率过大和温差过大" 32 "bit5:采样线掉线和过温" 64 "bit6:采样线掉线和温升速率过大" 128 "bit7采样线掉线和温差过大" ;
VAL_ 2333343609 S2A_TRDM_ThrmlRnwyFltCSC_57 1 "CSC1#" 2 "CSC2#" 3 "CSC3#" 4 "CSC4#" 5 "CSC5#" 6 "CSC6#" 7 "CSC7#" 8 "CSC8#" ;
VAL_ 2333343610 S2A_TRDM_ThrmlRnwyFltCseMsk_58 1 "bit0:欠压和过温" 2 "bit1:欠压和温升速率过大" 4 "bit2:欠压和温差过大" 8 "bit3:温升速率过大和过温" 16 "bit4:温升速率过大和温差过大" 32 "bit5:采样线掉线和过温" 64 "bit6:采样线掉线和温升速率过大" 128 "bit7采样线掉线和温差过大" ;
VAL_ 2333343610 S2A_TRDM_ThrmlRnwyFltCSC_58 1 "CSC1#" 2 "CSC2#" 3 "CSC3#" 4 "CSC4#" 5 "CSC5#" 6 "CSC6#" 7 "CSC7#" 8 "CSC8#" ;
VAL_ 2333343611 S2A_TRDM_ThrmlRnwyFltCseMsk_59 1 "bit0:欠压和过温" 2 "bit1:欠压和温升速率过大" 4 "bit2:欠压和温差过大" 8 "bit3:温升速率过大和过温" 16 "bit4:温升速率过大和温差过大" 32 "bit5:采样线掉线和过温" 64 "bit6:采样线掉线和温升速率过大" 128 "bit7采样线掉线和温差过大" ;
VAL_ 2333343611 S2A_TRDM_ThrmlRnwyFltCSC_59 1 "CSC1#" 2 "CSC2#" 3 "CSC3#" 4 "CSC4#" 5 "CSC5#" 6 "CSC6#" 7 "CSC7#" 8 "CSC8#" ;
VAL_ 2333343612 S2A_TRDM_ThrmlRnwyFltCseMsk_60 1 "bit0:欠压和过温" 2 "bit1:欠压和温升速率过大" 4 "bit2:欠压和温差过大" 8 "bit3:温升速率过大和过温" 16 "bit4:温升速率过大和温差过大" 32 "bit5:采样线掉线和过温" 64 "bit6:采样线掉线和温升速率过大" 128 "bit7采样线掉线和温差过大" ;
VAL_ 2333343612 S2A_TRDM_ThrmlRnwyFltCSC_60 1 "CSC1#" 2 "CSC2#" 3 "CSC3#" 4 "CSC4#" 5 "CSC5#" 6 "CSC6#" 7 "CSC7#" 8 "CSC8#" ;
VAL_ 2333343613 S2A_TRDM_ThrmlRnwyFltCseMsk_61 1 "bit0:欠压和过温" 2 "bit1:欠压和温升速率过大" 4 "bit2:欠压和温差过大" 8 "bit3:温升速率过大和过温" 16 "bit4:温升速率过大和温差过大" 32 "bit5:采样线掉线和过温" 64 "bit6:采样线掉线和温升速率过大" 128 "bit7采样线掉线和温差过大" ;
VAL_ 2333343613 S2A_TRDM_ThrmlRnwyFltCSC_61 1 "CSC1#" 2 "CSC2#" 3 "CSC3#" 4 "CSC4#" 5 "CSC5#" 6 "CSC6#" 7 "CSC7#" 8 "CSC8#" ;
VAL_ 2333343614 S2A_TRDM_ThrmlRnwyFltCseMsk_62 1 "bit0:欠压和过温" 2 "bit1:欠压和温升速率过大" 4 "bit2:欠压和温差过大" 8 "bit3:温升速率过大和过温" 16 "bit4:温升速率过大和温差过大" 32 "bit5:采样线掉线和过温" 64 "bit6:采样线掉线和温升速率过大" 128 "bit7采样线掉线和温差过大" ;
VAL_ 2333343614 S2A_TRDM_ThrmlRnwyFltCSC_62 1 "CSC1#" 2 "CSC2#" 3 "CSC3#" 4 "CSC4#" 5 "CSC5#" 6 "CSC6#" 7 "CSC7#" 8 "CSC8#" ;
VAL_ 2333343615 S2A_TRDM_ThrmlRnwyFltCseMsk_63 1 "bit0:欠压和过温" 2 "bit1:欠压和温升速率过大" 4 "bit2:欠压和温差过大" 8 "bit3:温升速率过大和过温" 16 "bit4:温升速率过大和温差过大" 32 "bit5:采样线掉线和过温" 64 "bit6:采样线掉线和温升速率过大" 128 "bit7采样线掉线和温差过大" ;
VAL_ 2333343615 S2A_TRDM_ThrmlRnwyFltCSC_63 1 "CSC1#" 2 "CSC2#" 3 "CSC3#" 4 "CSC4#" 5 "CSC5#" 6 "CSC6#" 7 "CSC7#" 8 "CSC8#" ;
VAL_ 2333474625 BAT_SysremainEngy_Charge_01 65535 "Invalid" ;
VAL_ 2333474625 BAT_SysremainEngy_DisCharge_01 65535 "Invalid" ;
VAL_ 2333474625 BAT_SOE_Charge_01 1023 "Invalid" ;
VAL_ 2333474625 BAT_SOE_DisCharge_01 1023 "Invalid" ;
VAL_ 2333474625 S2A_StepChrMode_01 0 "Disable" 1 "Enable" ;
VAL_ 2333474626 BAT_SysremainEngy_Charge_02 65535 "Invalid" ;
VAL_ 2333474626 BAT_SysremainEngy_DisCharge_02 65535 "Invalid" ;
VAL_ 2333474626 BAT_SOE_Charge_02 1023 "Invalid" ;
VAL_ 2333474626 BAT_SOE_DisCharge_02 1023 "Invalid" ;
VAL_ 2333474626 S2A_StepChrMode_02 0 "Disable" 1 "Enable" ;
VAL_ 2333474627 BAT_SysremainEngy_Charge_03 65535 "Invalid" ;
VAL_ 2333474627 BAT_SysremainEngy_DisCharge_03 65535 "Invalid" ;
VAL_ 2333474627 BAT_SOE_Charge_03 1023 "Invalid" ;
VAL_ 2333474627 BAT_SOE_DisCharge_03 1023 "Invalid" ;
VAL_ 2333474627 S2A_StepChrMode_03 0 "Disable" 1 "Enable" ;
VAL_ 2333474628 BAT_SysremainEngy_Charge_04 65535 "Invalid" ;
VAL_ 2333474628 BAT_SysremainEngy_DisCharge_04 65535 "Invalid" ;
VAL_ 2333474628 BAT_SOE_Charge_04 1023 "Invalid" ;
VAL_ 2333474628 BAT_SOE_DisCharge_04 1023 "Invalid" ;
VAL_ 2333474628 S2A_StepChrMode_04 0 "Disable" 1 "Enable" ;
VAL_ 2333474629 BAT_SysremainEngy_Charge_05 65535 "Invalid" ;
VAL_ 2333474629 BAT_SysremainEngy_DisCharge_05 65535 "Invalid" ;
VAL_ 2333474629 BAT_SOE_Charge_05 1023 "Invalid" ;
VAL_ 2333474629 BAT_SOE_DisCharge_05 1023 "Invalid" ;
VAL_ 2333474629 S2A_StepChrMode_05 0 "Disable" 1 "Enable" ;
VAL_ 2333474630 BAT_SysremainEngy_Charge_06 65535 "Invalid" ;
VAL_ 2333474630 BAT_SysremainEngy_DisCharge_06 65535 "Invalid" ;
VAL_ 2333474630 BAT_SOE_Charge_06 1023 "Invalid" ;
VAL_ 2333474630 BAT_SOE_DisCharge_06 1023 "Invalid" ;
VAL_ 2333474630 S2A_StepChrMode_06 0 "Disable" 1 "Enable" ;
VAL_ 2333474631 BAT_SysremainEngy_Charge_07 65535 "Invalid" ;
VAL_ 2333474631 BAT_SysremainEngy_DisCharge_07 65535 "Invalid" ;
VAL_ 2333474631 BAT_SOE_Charge_07 1023 "Invalid" ;
VAL_ 2333474631 BAT_SOE_DisCharge_07 1023 "Invalid" ;
VAL_ 2333474631 S2A_StepChrMode_07 0 "Disable" 1 "Enable" ;
VAL_ 2333474632 BAT_SysremainEngy_Charge_08 65535 "Invalid" ;
VAL_ 2333474632 BAT_SysremainEngy_DisCharge_08 65535 "Invalid" ;
VAL_ 2333474632 BAT_SOE_Charge_08 1023 "Invalid" ;
VAL_ 2333474632 BAT_SOE_DisCharge_08 1023 "Invalid" ;
VAL_ 2333474632 S2A_StepChrMode_08 0 "Disable" 1 "Enable" ;
VAL_ 2333474633 BAT_SysremainEngy_Charge_09 65535 "Invalid" ;
VAL_ 2333474633 BAT_SysremainEngy_DisCharge_09 65535 "Invalid" ;
VAL_ 2333474633 BAT_SOE_Charge_09 1023 "Invalid" ;
VAL_ 2333474633 BAT_SOE_DisCharge_09 1023 "Invalid" ;
VAL_ 2333474633 S2A_StepChrMode_09 0 "Disable" 1 "Enable" ;
VAL_ 2333474634 BAT_SysremainEngy_Charge_10 65535 "Invalid" ;
VAL_ 2333474634 BAT_SysremainEngy_DisCharge_10 65535 "Invalid" ;
VAL_ 2333474634 BAT_SOE_Charge_10 1023 "Invalid" ;
VAL_ 2333474634 BAT_SOE_DisCharge_10 1023 "Invalid" ;
VAL_ 2333474634 S2A_StepChrMode_10 0 "Disable" 1 "Enable" ;
VAL_ 2333474635 BAT_SysremainEngy_Charge_11 65535 "Invalid" ;
VAL_ 2333474635 BAT_SysremainEngy_DisCharge_11 65535 "Invalid" ;
VAL_ 2333474635 BAT_SOE_Charge_11 1023 "Invalid" ;
VAL_ 2333474635 BAT_SOE_DisCharge_11 1023 "Invalid" ;
VAL_ 2333474635 S2A_StepChrMode_11 0 "Disable" 1 "Enable" ;
VAL_ 2333474636 BAT_SysremainEngy_Charge_12 65535 "Invalid" ;
VAL_ 2333474636 BAT_SysremainEngy_DisCharge_12 65535 "Invalid" ;
VAL_ 2333474636 BAT_SOE_Charge_12 1023 "Invalid" ;
VAL_ 2333474636 BAT_SOE_DisCharge_12 1023 "Invalid" ;
VAL_ 2333474636 S2A_StepChrMode_12 0 "Disable" 1 "Enable" ;
VAL_ 2333474637 BAT_SysremainEngy_Charge_13 65535 "Invalid" ;
VAL_ 2333474637 BAT_SysremainEngy_DisCharge_13 65535 "Invalid" ;
VAL_ 2333474637 BAT_SOE_Charge_13 1023 "Invalid" ;
VAL_ 2333474637 BAT_SOE_DisCharge_13 1023 "Invalid" ;
VAL_ 2333474637 S2A_StepChrMode_13 0 "Disable" 1 "Enable" ;
VAL_ 2333474638 BAT_SysremainEngy_Charge_14 65535 "Invalid" ;
VAL_ 2333474638 BAT_SysremainEngy_DisCharge_14 65535 "Invalid" ;
VAL_ 2333474638 BAT_SOE_Charge_14 1023 "Invalid" ;
VAL_ 2333474638 BAT_SOE_DisCharge_14 1023 "Invalid" ;
VAL_ 2333474638 S2A_StepChrMode_14 0 "Disable" 1 "Enable" ;
VAL_ 2333474639 BAT_SysremainEngy_Charge_15 65535 "Invalid" ;
VAL_ 2333474639 BAT_SysremainEngy_DisCharge_15 65535 "Invalid" ;
VAL_ 2333474639 BAT_SOE_Charge_15 1023 "Invalid" ;
VAL_ 2333474639 BAT_SOE_DisCharge_15 1023 "Invalid" ;
VAL_ 2333474639 S2A_StepChrMode_15 0 "Disable" 1 "Enable" ;
VAL_ 2333474640 BAT_SysremainEngy_Charge_16 65535 "Invalid" ;
VAL_ 2333474640 BAT_SysremainEngy_DisCharge_16 65535 "Invalid" ;
VAL_ 2333474640 BAT_SOE_Charge_16 1023 "Invalid" ;
VAL_ 2333474640 BAT_SOE_DisCharge_16 1023 "Invalid" ;
VAL_ 2333474640 S2A_StepChrMode_16 0 "Disable" 1 "Enable" ;
VAL_ 2333474641 BAT_SysremainEngy_Charge_17 65535 "Invalid" ;
VAL_ 2333474641 BAT_SysremainEngy_DisCharge_17 65535 "Invalid" ;
VAL_ 2333474641 BAT_SOE_Charge_17 1023 "Invalid" ;
VAL_ 2333474641 BAT_SOE_DisCharge_17 1023 "Invalid" ;
VAL_ 2333474641 S2A_StepChrMode_17 0 "Disable" 1 "Enable" ;
VAL_ 2333474642 BAT_SysremainEngy_Charge_18 65535 "Invalid" ;
VAL_ 2333474642 BAT_SysremainEngy_DisCharge_18 65535 "Invalid" ;
VAL_ 2333474642 BAT_SOE_Charge_18 1023 "Invalid" ;
VAL_ 2333474642 BAT_SOE_DisCharge_18 1023 "Invalid" ;
VAL_ 2333474642 S2A_StepChrMode_18 0 "Disable" 1 "Enable" ;
VAL_ 2333474643 BAT_SysremainEngy_Charge_19 65535 "Invalid" ;
VAL_ 2333474643 BAT_SysremainEngy_DisCharge_19 65535 "Invalid" ;
VAL_ 2333474643 BAT_SOE_Charge_19 1023 "Invalid" ;
VAL_ 2333474643 BAT_SOE_DisCharge_19 1023 "Invalid" ;
VAL_ 2333474643 S2A_StepChrMode_19 0 "Disable" 1 "Enable" ;
VAL_ 2333474644 BAT_SysremainEngy_Charge_20 65535 "Invalid" ;
VAL_ 2333474644 BAT_SysremainEngy_DisCharge_20 65535 "Invalid" ;
VAL_ 2333474644 BAT_SOE_Charge_20 1023 "Invalid" ;
VAL_ 2333474644 BAT_SOE_DisCharge_20 1023 "Invalid" ;
VAL_ 2333474644 S2A_StepChrMode_20 0 "Disable" 1 "Enable" ;
VAL_ 2333474645 BAT_SysremainEngy_Charge_21 65535 "Invalid" ;
VAL_ 2333474645 BAT_SysremainEngy_DisCharge_21 65535 "Invalid" ;
VAL_ 2333474645 BAT_SOE_Charge_21 1023 "Invalid" ;
VAL_ 2333474645 BAT_SOE_DisCharge_21 1023 "Invalid" ;
VAL_ 2333474645 S2A_StepChrMode_21 0 "Disable" 1 "Enable" ;
VAL_ 2333474646 BAT_SysremainEngy_Charge_22 65535 "Invalid" ;
VAL_ 2333474646 BAT_SysremainEngy_DisCharge_22 65535 "Invalid" ;
VAL_ 2333474646 BAT_SOE_Charge_22 1023 "Invalid" ;
VAL_ 2333474646 BAT_SOE_DisCharge_22 1023 "Invalid" ;
VAL_ 2333474646 S2A_StepChrMode_22 0 "Disable" 1 "Enable" ;
VAL_ 2333474647 BAT_SysremainEngy_Charge_23 65535 "Invalid" ;
VAL_ 2333474647 BAT_SysremainEngy_DisCharge_23 65535 "Invalid" ;
VAL_ 2333474647 BAT_SOE_Charge_23 1023 "Invalid" ;
VAL_ 2333474647 BAT_SOE_DisCharge_23 1023 "Invalid" ;
VAL_ 2333474647 S2A_StepChrMode_23 0 "Disable" 1 "Enable" ;
VAL_ 2333474648 BAT_SysremainEngy_Charge_24 65535 "Invalid" ;
VAL_ 2333474648 BAT_SysremainEngy_DisCharge_24 65535 "Invalid" ;
VAL_ 2333474648 BAT_SOE_Charge_24 1023 "Invalid" ;
VAL_ 2333474648 BAT_SOE_DisCharge_24 1023 "Invalid" ;
VAL_ 2333474648 S2A_StepChrMode_24 0 "Disable" 1 "Enable" ;
VAL_ 2333474649 BAT_SysremainEngy_Charge_25 65535 "Invalid" ;
VAL_ 2333474649 BAT_SysremainEngy_DisCharge_25 65535 "Invalid" ;
VAL_ 2333474649 BAT_SOE_Charge_25 1023 "Invalid" ;
VAL_ 2333474649 BAT_SOE_DisCharge_25 1023 "Invalid" ;
VAL_ 2333474649 S2A_StepChrMode_25 0 "Disable" 1 "Enable" ;
VAL_ 2333474650 BAT_SysremainEngy_Charge_26 65535 "Invalid" ;
VAL_ 2333474650 BAT_SysremainEngy_DisCharge_26 65535 "Invalid" ;
VAL_ 2333474650 BAT_SOE_Charge_26 1023 "Invalid" ;
VAL_ 2333474650 BAT_SOE_DisCharge_26 1023 "Invalid" ;
VAL_ 2333474650 S2A_StepChrMode_26 0 "Disable" 1 "Enable" ;
VAL_ 2333474651 BAT_SysremainEngy_Charge_27 65535 "Invalid" ;
VAL_ 2333474651 BAT_SysremainEngy_DisCharge_27 65535 "Invalid" ;
VAL_ 2333474651 BAT_SOE_Charge_27 1023 "Invalid" ;
VAL_ 2333474651 BAT_SOE_DisCharge_27 1023 "Invalid" ;
VAL_ 2333474651 S2A_StepChrMode_27 0 "Disable" 1 "Enable" ;
VAL_ 2333474652 BAT_SysremainEngy_Charge_28 65535 "Invalid" ;
VAL_ 2333474652 BAT_SysremainEngy_DisCharge_28 65535 "Invalid" ;
VAL_ 2333474652 BAT_SOE_Charge_28 1023 "Invalid" ;
VAL_ 2333474652 BAT_SOE_DisCharge_28 1023 "Invalid" ;
VAL_ 2333474652 S2A_StepChrMode_28 0 "Disable" 1 "Enable" ;
VAL_ 2333474653 BAT_SysremainEngy_Charge_29 65535 "Invalid" ;
VAL_ 2333474653 BAT_SysremainEngy_DisCharge_29 65535 "Invalid" ;
VAL_ 2333474653 BAT_SOE_Charge_29 1023 "Invalid" ;
VAL_ 2333474653 BAT_SOE_DisCharge_29 1023 "Invalid" ;
VAL_ 2333474653 S2A_StepChrMode_29 0 "Disable" 1 "Enable" ;
VAL_ 2333474654 BAT_SysremainEngy_Charge_30 65535 "Invalid" ;
VAL_ 2333474654 BAT_SysremainEngy_DisCharge_30 65535 "Invalid" ;
VAL_ 2333474654 BAT_SOE_Charge_30 1023 "Invalid" ;
VAL_ 2333474654 BAT_SOE_DisCharge_30 1023 "Invalid" ;
VAL_ 2333474654 S2A_StepChrMode_30 0 "Disable" 1 "Enable" ;
VAL_ 2333474655 BAT_SysremainEngy_Charge_31 65535 "Invalid" ;
VAL_ 2333474655 BAT_SysremainEngy_DisCharge_31 65535 "Invalid" ;
VAL_ 2333474655 BAT_SOE_Charge_31 1023 "Invalid" ;
VAL_ 2333474655 BAT_SOE_DisCharge_31 1023 "Invalid" ;
VAL_ 2333474655 S2A_StepChrMode_31 0 "Disable" 1 "Enable" ;
VAL_ 2333474656 BAT_SysremainEngy_Charge_32 65535 "Invalid" ;
VAL_ 2333474656 BAT_SysremainEngy_DisCharge_32 65535 "Invalid" ;
VAL_ 2333474656 BAT_SOE_Charge_32 1023 "Invalid" ;
VAL_ 2333474656 BAT_SOE_DisCharge_32 1023 "Invalid" ;
VAL_ 2333474656 S2A_StepChrMode_32 0 "Disable" 1 "Enable" ;
VAL_ 2333474657 BAT_SysremainEngy_Charge_33 65535 "Invalid" ;
VAL_ 2333474657 BAT_SysremainEngy_DisCharge_33 65535 "Invalid" ;
VAL_ 2333474657 BAT_SOE_Charge_33 1023 "Invalid" ;
VAL_ 2333474657 BAT_SOE_DisCharge_33 1023 "Invalid" ;
VAL_ 2333474657 S2A_StepChrMode_33 0 "Disable" 1 "Enable" ;
VAL_ 2333474658 BAT_SysremainEngy_Charge_34 65535 "Invalid" ;
VAL_ 2333474658 BAT_SysremainEngy_DisCharge_34 65535 "Invalid" ;
VAL_ 2333474658 BAT_SOE_Charge_34 1023 "Invalid" ;
VAL_ 2333474658 BAT_SOE_DisCharge_34 1023 "Invalid" ;
VAL_ 2333474658 S2A_StepChrMode_34 0 "Disable" 1 "Enable" ;
VAL_ 2333474659 BAT_SysremainEngy_Charge_35 65535 "Invalid" ;
VAL_ 2333474659 BAT_SysremainEngy_DisCharge_35 65535 "Invalid" ;
VAL_ 2333474659 BAT_SOE_Charge_35 1023 "Invalid" ;
VAL_ 2333474659 BAT_SOE_DisCharge_35 1023 "Invalid" ;
VAL_ 2333474659 S2A_StepChrMode_35 0 "Disable" 1 "Enable" ;
VAL_ 2333474660 BAT_SysremainEngy_Charge_36 65535 "Invalid" ;
VAL_ 2333474660 BAT_SysremainEngy_DisCharge_36 65535 "Invalid" ;
VAL_ 2333474660 BAT_SOE_Charge_36 1023 "Invalid" ;
VAL_ 2333474660 BAT_SOE_DisCharge_36 1023 "Invalid" ;
VAL_ 2333474660 S2A_StepChrMode_36 0 "Disable" 1 "Enable" ;
VAL_ 2333474661 BAT_SysremainEngy_Charge_37 65535 "Invalid" ;
VAL_ 2333474661 BAT_SysremainEngy_DisCharge_37 65535 "Invalid" ;
VAL_ 2333474661 BAT_SOE_Charge_37 1023 "Invalid" ;
VAL_ 2333474661 BAT_SOE_DisCharge_37 1023 "Invalid" ;
VAL_ 2333474661 S2A_StepChrMode_37 0 "Disable" 1 "Enable" ;
VAL_ 2333474662 BAT_SysremainEngy_Charge_38 65535 "Invalid" ;
VAL_ 2333474662 BAT_SysremainEngy_DisCharge_38 65535 "Invalid" ;
VAL_ 2333474662 BAT_SOE_Charge_38 1023 "Invalid" ;
VAL_ 2333474662 BAT_SOE_DisCharge_38 1023 "Invalid" ;
VAL_ 2333474662 S2A_StepChrMode_38 0 "Disable" 1 "Enable" ;
VAL_ 2333474663 BAT_SysremainEngy_Charge_39 65535 "Invalid" ;
VAL_ 2333474663 BAT_SysremainEngy_DisCharge_39 65535 "Invalid" ;
VAL_ 2333474663 BAT_SOE_Charge_39 1023 "Invalid" ;
VAL_ 2333474663 BAT_SOE_DisCharge_39 1023 "Invalid" ;
VAL_ 2333474663 S2A_StepChrMode_39 0 "Disable" 1 "Enable" ;
VAL_ 2333474664 BAT_SysremainEngy_Charge_40 65535 "Invalid" ;
VAL_ 2333474664 BAT_SysremainEngy_DisCharge_40 65535 "Invalid" ;
VAL_ 2333474664 BAT_SOE_Charge_40 1023 "Invalid" ;
VAL_ 2333474664 BAT_SOE_DisCharge_40 1023 "Invalid" ;
VAL_ 2333474664 S2A_StepChrMode_40 0 "Disable" 1 "Enable" ;
VAL_ 2333474665 BAT_SysremainEngy_Charge_41 65535 "Invalid" ;
VAL_ 2333474665 BAT_SysremainEngy_DisCharge_41 65535 "Invalid" ;
VAL_ 2333474665 BAT_SOE_Charge_41 1023 "Invalid" ;
VAL_ 2333474665 BAT_SOE_DisCharge_41 1023 "Invalid" ;
VAL_ 2333474665 S2A_StepChrMode_41 0 "Disable" 1 "Enable" ;
VAL_ 2333474666 BAT_SysremainEngy_Charge_42 65535 "Invalid" ;
VAL_ 2333474666 BAT_SysremainEngy_DisCharge_42 65535 "Invalid" ;
VAL_ 2333474666 BAT_SOE_Charge_42 1023 "Invalid" ;
VAL_ 2333474666 BAT_SOE_DisCharge_42 1023 "Invalid" ;
VAL_ 2333474666 S2A_StepChrMode_42 0 "Disable" 1 "Enable" ;
VAL_ 2333474667 BAT_SysremainEngy_Charge_43 65535 "Invalid" ;
VAL_ 2333474667 BAT_SysremainEngy_DisCharge_43 65535 "Invalid" ;
VAL_ 2333474667 BAT_SOE_Charge_43 1023 "Invalid" ;
VAL_ 2333474667 BAT_SOE_DisCharge_43 1023 "Invalid" ;
VAL_ 2333474667 S2A_StepChrMode_43 0 "Disable" 1 "Enable" ;
VAL_ 2333474668 BAT_SysremainEngy_Charge_44 65535 "Invalid" ;
VAL_ 2333474668 BAT_SysremainEngy_DisCharge_44 65535 "Invalid" ;
VAL_ 2333474668 BAT_SOE_Charge_44 1023 "Invalid" ;
VAL_ 2333474668 BAT_SOE_DisCharge_44 1023 "Invalid" ;
VAL_ 2333474668 S2A_StepChrMode_44 0 "Disable" 1 "Enable" ;
VAL_ 2333474669 BAT_SysremainEngy_Charge_45 65535 "Invalid" ;
VAL_ 2333474669 BAT_SysremainEngy_DisCharge_45 65535 "Invalid" ;
VAL_ 2333474669 BAT_SOE_Charge_45 1023 "Invalid" ;
VAL_ 2333474669 BAT_SOE_DisCharge_45 1023 "Invalid" ;
VAL_ 2333474669 S2A_StepChrMode_45 0 "Disable" 1 "Enable" ;
VAL_ 2333474670 BAT_SysremainEngy_Charge_46 65535 "Invalid" ;
VAL_ 2333474670 BAT_SysremainEngy_DisCharge_46 65535 "Invalid" ;
VAL_ 2333474670 BAT_SOE_Charge_46 1023 "Invalid" ;
VAL_ 2333474670 BAT_SOE_DisCharge_46 1023 "Invalid" ;
VAL_ 2333474670 S2A_StepChrMode_46 0 "Disable" 1 "Enable" ;
VAL_ 2333474671 BAT_SysremainEngy_Charge_47 65535 "Invalid" ;
VAL_ 2333474671 BAT_SysremainEngy_DisCharge_47 65535 "Invalid" ;
VAL_ 2333474671 BAT_SOE_Charge_47 1023 "Invalid" ;
VAL_ 2333474671 BAT_SOE_DisCharge_47 1023 "Invalid" ;
VAL_ 2333474671 S2A_StepChrMode_47 0 "Disable" 1 "Enable" ;
VAL_ 2333474672 BAT_SysremainEngy_Charge_48 65535 "Invalid" ;
VAL_ 2333474672 BAT_SysremainEngy_DisCharge_48 65535 "Invalid" ;
VAL_ 2333474672 BAT_SOE_Charge_48 1023 "Invalid" ;
VAL_ 2333474672 BAT_SOE_DisCharge_48 1023 "Invalid" ;
VAL_ 2333474672 S2A_StepChrMode_48 0 "Disable" 1 "Enable" ;
VAL_ 2333474673 BAT_SysremainEngy_Charge_49 65535 "Invalid" ;
VAL_ 2333474673 BAT_SysremainEngy_DisCharge_49 65535 "Invalid" ;
VAL_ 2333474673 BAT_SOE_Charge_49 1023 "Invalid" ;
VAL_ 2333474673 BAT_SOE_DisCharge_49 1023 "Invalid" ;
VAL_ 2333474673 S2A_StepChrMode_49 0 "Disable" 1 "Enable" ;
VAL_ 2333474674 BAT_SysremainEngy_Charge_50 65535 "Invalid" ;
VAL_ 2333474674 BAT_SysremainEngy_DisCharge_50 65535 "Invalid" ;
VAL_ 2333474674 BAT_SOE_Charge_50 1023 "Invalid" ;
VAL_ 2333474674 BAT_SOE_DisCharge_50 1023 "Invalid" ;
VAL_ 2333474674 S2A_StepChrMode_50 0 "Disable" 1 "Enable" ;
VAL_ 2333474675 BAT_SysremainEngy_Charge_51 65535 "Invalid" ;
VAL_ 2333474675 BAT_SysremainEngy_DisCharge_51 65535 "Invalid" ;
VAL_ 2333474675 BAT_SOE_Charge_51 1023 "Invalid" ;
VAL_ 2333474675 BAT_SOE_DisCharge_51 1023 "Invalid" ;
VAL_ 2333474675 S2A_StepChrMode_51 0 "Disable" 1 "Enable" ;
VAL_ 2333474676 BAT_SysremainEngy_Charge_52 65535 "Invalid" ;
VAL_ 2333474676 BAT_SysremainEngy_DisCharge_52 65535 "Invalid" ;
VAL_ 2333474676 BAT_SOE_Charge_52 1023 "Invalid" ;
VAL_ 2333474676 BAT_SOE_DisCharge_52 1023 "Invalid" ;
VAL_ 2333474676 S2A_StepChrMode_52 0 "Disable" 1 "Enable" ;
VAL_ 2333474677 BAT_SysremainEngy_Charge_53 65535 "Invalid" ;
VAL_ 2333474677 BAT_SysremainEngy_DisCharge_53 65535 "Invalid" ;
VAL_ 2333474677 BAT_SOE_Charge_53 1023 "Invalid" ;
VAL_ 2333474677 BAT_SOE_DisCharge_53 1023 "Invalid" ;
VAL_ 2333474677 S2A_StepChrMode_53 0 "Disable" 1 "Enable" ;
VAL_ 2333474678 BAT_SysremainEngy_Charge_54 65535 "Invalid" ;
VAL_ 2333474678 BAT_SysremainEngy_DisCharge_54 65535 "Invalid" ;
VAL_ 2333474678 BAT_SOE_Charge_54 1023 "Invalid" ;
VAL_ 2333474678 BAT_SOE_DisCharge_54 1023 "Invalid" ;
VAL_ 2333474678 S2A_StepChrMode_54 0 "Disable" 1 "Enable" ;
VAL_ 2333474679 BAT_SysremainEngy_Charge_55 65535 "Invalid" ;
VAL_ 2333474679 BAT_SysremainEngy_DisCharge_55 65535 "Invalid" ;
VAL_ 2333474679 BAT_SOE_Charge_55 1023 "Invalid" ;
VAL_ 2333474679 BAT_SOE_DisCharge_55 1023 "Invalid" ;
VAL_ 2333474679 S2A_StepChrMode_55 0 "Disable" 1 "Enable" ;
VAL_ 2333474680 BAT_SysremainEngy_Charge_56 65535 "Invalid" ;
VAL_ 2333474680 BAT_SysremainEngy_DisCharge_56 65535 "Invalid" ;
VAL_ 2333474680 BAT_SOE_Charge_56 1023 "Invalid" ;
VAL_ 2333474680 BAT_SOE_DisCharge_56 1023 "Invalid" ;
VAL_ 2333474680 S2A_StepChrMode_56 0 "Disable" 1 "Enable" ;
VAL_ 2333474681 BAT_SysremainEngy_Charge_57 65535 "Invalid" ;
VAL_ 2333474681 BAT_SysremainEngy_DisCharge_57 65535 "Invalid" ;
VAL_ 2333474681 BAT_SOE_Charge_57 1023 "Invalid" ;
VAL_ 2333474681 BAT_SOE_DisCharge_57 1023 "Invalid" ;
VAL_ 2333474681 S2A_StepChrMode_57 0 "Disable" 1 "Enable" ;
VAL_ 2333474682 BAT_SysremainEngy_Charge_58 65535 "Invalid" ;
VAL_ 2333474682 BAT_SysremainEngy_DisCharge_58 65535 "Invalid" ;
VAL_ 2333474682 BAT_SOE_Charge_58 1023 "Invalid" ;
VAL_ 2333474682 BAT_SOE_DisCharge_58 1023 "Invalid" ;
VAL_ 2333474682 S2A_StepChrMode_58 0 "Disable" 1 "Enable" ;
VAL_ 2333474683 BAT_SysremainEngy_Charge_59 65535 "Invalid" ;
VAL_ 2333474683 BAT_SysremainEngy_DisCharge_59 65535 "Invalid" ;
VAL_ 2333474683 BAT_SOE_Charge_59 1023 "Invalid" ;
VAL_ 2333474683 BAT_SOE_DisCharge_59 1023 "Invalid" ;
VAL_ 2333474683 S2A_StepChrMode_59 0 "Disable" 1 "Enable" ;
VAL_ 2333474684 BAT_SysremainEngy_Charge_60 65535 "Invalid" ;
VAL_ 2333474684 BAT_SysremainEngy_DisCharge_60 65535 "Invalid" ;
VAL_ 2333474684 BAT_SOE_Charge_60 1023 "Invalid" ;
VAL_ 2333474684 BAT_SOE_DisCharge_60 1023 "Invalid" ;
VAL_ 2333474684 S2A_StepChrMode_60 0 "Disable" 1 "Enable" ;
VAL_ 2333474685 BAT_SysremainEngy_Charge_61 65535 "Invalid" ;
VAL_ 2333474685 BAT_SysremainEngy_DisCharge_61 65535 "Invalid" ;
VAL_ 2333474685 BAT_SOE_Charge_61 1023 "Invalid" ;
VAL_ 2333474685 BAT_SOE_DisCharge_61 1023 "Invalid" ;
VAL_ 2333474685 S2A_StepChrMode_61 0 "Disable" 1 "Enable" ;
VAL_ 2333474686 BAT_SysremainEngy_Charge_62 65535 "Invalid" ;
VAL_ 2333474686 BAT_SysremainEngy_DisCharge_62 65535 "Invalid" ;
VAL_ 2333474686 BAT_SOE_Charge_62 1023 "Invalid" ;
VAL_ 2333474686 BAT_SOE_DisCharge_62 1023 "Invalid" ;
VAL_ 2333474686 S2A_StepChrMode_62 0 "Disable" 1 "Enable" ;
VAL_ 2333474687 BAT_SysremainEngy_Charge_63 65535 "Invalid" ;
VAL_ 2333474687 BAT_SysremainEngy_DisCharge_63 65535 "Invalid" ;
VAL_ 2333474687 BAT_SOE_Charge_63 1023 "Invalid" ;
VAL_ 2333474687 BAT_SOE_DisCharge_63 1023 "Invalid" ;
VAL_ 2333474687 S2A_StepChrMode_63 0 "Disable" 1 "Enable" ;
VERSION ""

NS_ :

BS_:

BU_: MBMU PC SBMU IMM ETH DCDC LEMS

BO_ 2333605714 S2A_SUMDATA17__18: 8 SBMU
 SG_ S2A_HisOVtimes_18 : 0|16@1+ (1,0) [0|65535] ""  MBMU
 SG_ S2A_HisUVtimes_18 : 16|16@1+ (1,0) [0|65535] ""  MBMU
 SG_ S2A_HisOCCtimes_18 : 32|16@1+ (1,0) [0|65535] ""  MBMU
 SG_ S2A_HisOCDtimes_18 : 48|16@1+ (1,0) [0|65535] ""  MBMU

BO_ 2333605715 S2A_SUMDATA17__19: 8 SBMU
 SG_ S2A_HisOVtimes_19 : 0|16@1+ (1,0) [0|65535] ""  MBMU
 SG_ S2A_HisUVtimes_19 : 16|16@1+ (1,0) [0|65535] ""  MBMU
 SG_ S2A_HisOCCtimes_19 : 32|16@1+ (1,0) [0|65535] ""  MBMU
 SG_ S2A_HisOCDtimes_19 : 48|16@1+ (1,0) [0|65535] ""  MBMU

BO_ 2333605716 S2A_SUMDATA17__20: 8 SBMU
 SG_ S2A_HisOVtimes_20 : 0|16@1+ (1,0) [0|65535] ""  MBMU
 SG_ S2A_HisUVtimes_20 : 16|16@1+ (1,0) [0|65535] ""  MBMU
 SG_ S2A_HisOCCtimes_20 : 32|16@1+ (1,0) [0|65535] ""  MBMU
 SG_ S2A_HisOCDtimes_20 : 48|16@1+ (1,0) [0|65535] ""  MBMU

BO_ 2333605717 S2A_SUMDATA17__21: 8 SBMU
 SG_ S2A_HisOVtimes_21 : 0|16@1+ (1,0) [0|65535] ""  MBMU
 SG_ S2A_HisUVtimes_21 : 16|16@1+ (1,0) [0|65535] ""  MBMU
 SG_ S2A_HisOCCtimes_21 : 32|16@1+ (1,0) [0|65535] ""  MBMU
 SG_ S2A_HisOCDtimes_21 : 48|16@1+ (1,0) [0|65535] ""  MBMU

BO_ 2333605718 S2A_SUMDATA17__22: 8 SBMU
 SG_ S2A_HisOVtimes_22 : 0|16@1+ (1,0) [0|65535] ""  MBMU
 SG_ S2A_HisUVtimes_22 : 16|16@1+ (1,0) [0|65535] ""  MBMU
 SG_ S2A_HisOCCtimes_22 : 32|16@1+ (1,0) [0|65535] ""  MBMU
 SG_ S2A_HisOCDtimes_22 : 48|16@1+ (1,0) [0|65535] ""  MBMU

BO_ 2333605719 S2A_SUMDATA17__23: 8 SBMU
 SG_ S2A_HisOVtimes_23 : 0|16@1+ (1,0) [0|65535] ""  MBMU
 SG_ S2A_HisUVtimes_23 : 16|16@1+ (1,0) [0|65535] ""  MBMU
 SG_ S2A_HisOCCtimes_23 : 32|16@1+ (1,0) [0|65535] ""  MBMU
 SG_ S2A_HisOCDtimes_23 : 48|16@1+ (1,0) [0|65535] ""  MBMU

BO_ 2333605720 S2A_SUMDATA17__24: 8 SBMU
 SG_ S2A_HisOVtimes_24 : 0|16@1+ (1,0) [0|65535] ""  MBMU
 SG_ S2A_HisUVtimes_24 : 16|16@1+ (1,0) [0|65535] ""  MBMU
 SG_ S2A_HisOCCtimes_24 : 32|16@1+ (1,0) [0|65535] ""  MBMU
 SG_ S2A_HisOCDtimes_24 : 48|16@1+ (1,0) [0|65535] ""  MBMU

BO_ 2333605721 S2A_SUMDATA17__25: 8 SBMU
 SG_ S2A_HisOVtimes_25 : 0|16@1+ (1,0) [0|65535] ""  MBMU
 SG_ S2A_HisUVtimes_25 : 16|16@1+ (1,0) [0|65535] ""  MBMU
 SG_ S2A_HisOCCtimes_25 : 32|16@1+ (1,0) [0|65535] ""  MBMU
 SG_ S2A_HisOCDtimes_25 : 48|16@1+ (1,0) [0|65535] ""  MBMU

BO_ 2333605722 S2A_SUMDATA17__26: 8 SBMU
 SG_ S2A_HisOVtimes_26 : 0|16@1+ (1,0) [0|65535] ""  MBMU
 SG_ S2A_HisUVtimes_26 : 16|16@1+ (1,0) [0|65535] ""  MBMU
 SG_ S2A_HisOCCtimes_26 : 32|16@1+ (1,0) [0|65535] ""  MBMU
 SG_ S2A_HisOCDtimes_26 : 48|16@1+ (1,0) [0|65535] ""  MBMU

BO_ 2333605723 S2A_SUMDATA17__27: 8 SBMU
 SG_ S2A_HisOVtimes_27 : 0|16@1+ (1,0) [0|65535] ""  MBMU
 SG_ S2A_HisUVtimes_27 : 16|16@1+ (1,0) [0|65535] ""  MBMU
 SG_ S2A_HisOCCtimes_27 : 32|16@1+ (1,0) [0|65535] ""  MBMU
 SG_ S2A_HisOCDtimes_27 : 48|16@1+ (1,0) [0|65535] ""  MBMU

BO_ 2333605724 S2A_SUMDATA17__28: 8 SBMU
 SG_ S2A_HisOVtimes_28 : 0|16@1+ (1,0) [0|65535] ""  MBMU
 SG_ S2A_HisUVtimes_28 : 16|16@1+ (1,0) [0|65535] ""  MBMU
 SG_ S2A_HisOCCtimes_28 : 32|16@1+ (1,0) [0|65535] ""  MBMU
 SG_ S2A_HisOCDtimes_28 : 48|16@1+ (1,0) [0|65535] ""  MBMU

BO_ 2333605725 S2A_SUMDATA17__29: 8 SBMU
 SG_ S2A_HisOVtimes_29 : 0|16@1+ (1,0) [0|65535] ""  MBMU
 SG_ S2A_HisUVtimes_29 : 16|16@1+ (1,0) [0|65535] ""  MBMU
 SG_ S2A_HisOCCtimes_29 : 32|16@1+ (1,0) [0|65535] ""  MBMU
 SG_ S2A_HisOCDtimes_29 : 48|16@1+ (1,0) [0|65535] ""  MBMU

BO_ 2333605726 S2A_SUMDATA17__30: 8 SBMU
 SG_ S2A_HisOVtimes_30 : 0|16@1+ (1,0) [0|65535] ""  MBMU
 SG_ S2A_HisUVtimes_30 : 16|16@1+ (1,0) [0|65535] ""  MBMU
 SG_ S2A_HisOCCtimes_30 : 32|16@1+ (1,0) [0|65535] ""  MBMU
 SG_ S2A_HisOCDtimes_30 : 48|16@1+ (1,0) [0|65535] ""  MBMU

BO_ 2333605727 S2A_SUMDATA17__31: 8 SBMU
 SG_ S2A_HisOVtimes_31 : 0|16@1+ (1,0) [0|65535] ""  MBMU
 SG_ S2A_HisUVtimes_31 : 16|16@1+ (1,0) [0|65535] ""  MBMU
 SG_ S2A_HisOCCtimes_31 : 32|16@1+ (1,0) [0|65535] ""  MBMU
 SG_ S2A_HisOCDtimes_31 : 48|16@1+ (1,0) [0|65535] ""  MBMU

BO_ 2333605728 S2A_SUMDATA17__32: 8 SBMU
 SG_ S2A_HisOVtimes_32 : 0|16@1+ (1,0) [0|65535] ""  MBMU
 SG_ S2A_HisUVtimes_32 : 16|16@1+ (1,0) [0|65535] ""  MBMU
 SG_ S2A_HisOCCtimes_32 : 32|16@1+ (1,0) [0|65535] ""  MBMU
 SG_ S2A_HisOCDtimes_32 : 48|16@1+ (1,0) [0|65535] ""  MBMU

BO_ 2333605729 S2A_SUMDATA17__33: 8 SBMU
 SG_ S2A_HisOVtimes_33 : 0|16@1+ (1,0) [0|65535] ""  MBMU
 SG_ S2A_HisUVtimes_33 : 16|16@1+ (1,0) [0|65535] ""  MBMU
 SG_ S2A_HisOCCtimes_33 : 32|16@1+ (1,0) [0|65535] ""  MBMU
 SG_ S2A_HisOCDtimes_33 : 48|16@1+ (1,0) [0|65535] ""  MBMU

BO_ 2333605730 S2A_SUMDATA17__34: 8 SBMU
 SG_ S2A_HisOVtimes_34 : 0|16@1+ (1,0) [0|65535] ""  MBMU
 SG_ S2A_HisUVtimes_34 : 16|16@1+ (1,0) [0|65535] ""  MBMU
 SG_ S2A_HisOCCtimes_34 : 32|16@1+ (1,0) [0|65535] ""  MBMU
 SG_ S2A_HisOCDtimes_34 : 48|16@1+ (1,0) [0|65535] ""  MBMU

BO_ 2333605731 S2A_SUMDATA17__35: 8 SBMU
 SG_ S2A_HisOVtimes_35 : 0|16@1+ (1,0) [0|65535] ""  MBMU
 SG_ S2A_HisUVtimes_35 : 16|16@1+ (1,0) [0|65535] ""  MBMU
 SG_ S2A_HisOCCtimes_35 : 32|16@1+ (1,0) [0|65535] ""  MBMU
 SG_ S2A_HisOCDtimes_35 : 48|16@1+ (1,0) [0|65535] ""  MBMU

BO_ 2333605732 S2A_SUMDATA17__36: 8 SBMU
 SG_ S2A_HisOVtimes_36 : 0|16@1+ (1,0) [0|65535] ""  MBMU
 SG_ S2A_HisUVtimes_36 : 16|16@1+ (1,0) [0|65535] ""  MBMU
 SG_ S2A_HisOCCtimes_36 : 32|16@1+ (1,0) [0|65535] ""  MBMU
 SG_ S2A_HisOCDtimes_36 : 48|16@1+ (1,0) [0|65535] ""  MBMU

BO_ 2333605733 S2A_SUMDATA17__37: 8 SBMU
 SG_ S2A_HisOVtimes_37 : 0|16@1+ (1,0) [0|65535] ""  MBMU
 SG_ S2A_HisUVtimes_37 : 16|16@1+ (1,0) [0|65535] ""  MBMU
 SG_ S2A_HisOCCtimes_37 : 32|16@1+ (1,0) [0|65535] ""  MBMU
 SG_ S2A_HisOCDtimes_37 : 48|16@1+ (1,0) [0|65535] ""  MBMU

BO_ 2333605734 S2A_SUMDATA17__38: 8 SBMU
 SG_ S2A_HisOVtimes_38 : 0|16@1+ (1,0) [0|65535] ""  MBMU
 SG_ S2A_HisUVtimes_38 : 16|16@1+ (1,0) [0|65535] ""  MBMU
 SG_ S2A_HisOCCtimes_38 : 32|16@1+ (1,0) [0|65535] ""  MBMU
 SG_ S2A_HisOCDtimes_38 : 48|16@1+ (1,0) [0|65535] ""  MBMU

BO_ 2333605735 S2A_SUMDATA17__39: 8 SBMU
 SG_ S2A_HisOVtimes_39 : 0|16@1+ (1,0) [0|65535] ""  MBMU
 SG_ S2A_HisUVtimes_39 : 16|16@1+ (1,0) [0|65535] ""  MBMU
 SG_ S2A_HisOCCtimes_39 : 32|16@1+ (1,0) [0|65535] ""  MBMU
 SG_ S2A_HisOCDtimes_39 : 48|16@1+ (1,0) [0|65535] ""  MBMU

BO_ 2333605736 S2A_SUMDATA17__40: 8 SBMU
 SG_ S2A_HisOVtimes_40 : 0|16@1+ (1,0) [0|65535] ""  MBMU
 SG_ S2A_HisUVtimes_40 : 16|16@1+ (1,0) [0|65535] ""  MBMU
 SG_ S2A_HisOCCtimes_40 : 32|16@1+ (1,0) [0|65535] ""  MBMU
 SG_ S2A_HisOCDtimes_40 : 48|16@1+ (1,0) [0|65535] ""  MBMU

BO_ 2333605737 S2A_SUMDATA17__41: 8 SBMU
 SG_ S2A_HisOVtimes_41 : 0|16@1+ (1,0) [0|65535] ""  MBMU
 SG_ S2A_HisUVtimes_41 : 16|16@1+ (1,0) [0|65535] ""  MBMU
 SG_ S2A_HisOCCtimes_41 : 32|16@1+ (1,0) [0|65535] ""  MBMU
 SG_ S2A_HisOCDtimes_41 : 48|16@1+ (1,0) [0|65535] ""  MBMU

BO_ 2333605738 S2A_SUMDATA17__42: 8 SBMU
 SG_ S2A_HisOVtimes_42 : 0|16@1+ (1,0) [0|65535] ""  MBMU
 SG_ S2A_HisUVtimes_42 : 16|16@1+ (1,0) [0|65535] ""  MBMU
 SG_ S2A_HisOCCtimes_42 : 32|16@1+ (1,0) [0|65535] ""  MBMU
 SG_ S2A_HisOCDtimes_42 : 48|16@1+ (1,0) [0|65535] ""  MBMU

BO_ 2333605739 S2A_SUMDATA17__43: 8 SBMU
 SG_ S2A_HisOVtimes_43 : 0|16@1+ (1,0) [0|65535] ""  MBMU
 SG_ S2A_HisUVtimes_43 : 16|16@1+ (1,0) [0|65535] ""  MBMU
 SG_ S2A_HisOCCtimes_43 : 32|16@1+ (1,0) [0|65535] ""  MBMU
 SG_ S2A_HisOCDtimes_43 : 48|16@1+ (1,0) [0|65535] ""  MBMU

BO_ 2333605740 S2A_SUMDATA17__44: 8 SBMU
 SG_ S2A_HisOVtimes_44 : 0|16@1+ (1,0) [0|65535] ""  MBMU
 SG_ S2A_HisUVtimes_44 : 16|16@1+ (1,0) [0|65535] ""  MBMU
 SG_ S2A_HisOCCtimes_44 : 32|16@1+ (1,0) [0|65535] ""  MBMU
 SG_ S2A_HisOCDtimes_44 : 48|16@1+ (1,0) [0|65535] ""  MBMU

BO_ 2333605741 S2A_SUMDATA17__45: 8 SBMU
 SG_ S2A_HisOVtimes_45 : 0|16@1+ (1,0) [0|65535] ""  MBMU
 SG_ S2A_HisUVtimes_45 : 16|16@1+ (1,0) [0|65535] ""  MBMU
 SG_ S2A_HisOCCtimes_45 : 32|16@1+ (1,0) [0|65535] ""  MBMU
 SG_ S2A_HisOCDtimes_45 : 48|16@1+ (1,0) [0|65535] ""  MBMU

BO_ 2333605742 S2A_SUMDATA17__46: 8 SBMU
 SG_ S2A_HisOVtimes_46 : 0|16@1+ (1,0) [0|65535] ""  MBMU
 SG_ S2A_HisUVtimes_46 : 16|16@1+ (1,0) [0|65535] ""  MBMU
 SG_ S2A_HisOCCtimes_46 : 32|16@1+ (1,0) [0|65535] ""  MBMU
 SG_ S2A_HisOCDtimes_46 : 48|16@1+ (1,0) [0|65535] ""  MBMU

BO_ 2333605743 S2A_SUMDATA17__47: 8 SBMU
 SG_ S2A_HisOVtimes_47 : 0|16@1+ (1,0) [0|65535] ""  MBMU
 SG_ S2A_HisUVtimes_47 : 16|16@1+ (1,0) [0|65535] ""  MBMU
 SG_ S2A_HisOCCtimes_47 : 32|16@1+ (1,0) [0|65535] ""  MBMU
 SG_ S2A_HisOCDtimes_47 : 48|16@1+ (1,0) [0|65535] ""  MBMU

BO_ 2333605744 S2A_SUMDATA17__48: 8 SBMU
 SG_ S2A_HisOVtimes_48 : 0|16@1+ (1,0) [0|65535] ""  MBMU
 SG_ S2A_HisUVtimes_48 : 16|16@1+ (1,0) [0|65535] ""  MBMU
 SG_ S2A_HisOCCtimes_48 : 32|16@1+ (1,0) [0|65535] ""  MBMU
 SG_ S2A_HisOCDtimes_48 : 48|16@1+ (1,0) [0|65535] ""  MBMU

BO_ 2333605745 S2A_SUMDATA17__49: 8 SBMU
 SG_ S2A_HisOVtimes_49 : 0|16@1+ (1,0) [0|65535] ""  MBMU
 SG_ S2A_HisUVtimes_49 : 16|16@1+ (1,0) [0|65535] ""  MBMU
 SG_ S2A_HisOCCtimes_49 : 32|16@1+ (1,0) [0|65535] ""  MBMU
 SG_ S2A_HisOCDtimes_49 : 48|16@1+ (1,0) [0|65535] ""  MBMU

BO_ 2333605746 S2A_SUMDATA17__50: 8 SBMU
 SG_ S2A_HisOVtimes_50 : 0|16@1+ (1,0) [0|65535] ""  MBMU
 SG_ S2A_HisUVtimes_50 : 16|16@1+ (1,0) [0|65535] ""  MBMU
 SG_ S2A_HisOCCtimes_50 : 32|16@1+ (1,0) [0|65535] ""  MBMU
 SG_ S2A_HisOCDtimes_50 : 48|16@1+ (1,0) [0|65535] ""  MBMU

BO_ 2333605747 S2A_SUMDATA17__51: 8 SBMU
 SG_ S2A_HisOVtimes_51 : 0|16@1+ (1,0) [0|65535] ""  MBMU
 SG_ S2A_HisUVtimes_51 : 16|16@1+ (1,0) [0|65535] ""  MBMU
 SG_ S2A_HisOCCtimes_51 : 32|16@1+ (1,0) [0|65535] ""  MBMU
 SG_ S2A_HisOCDtimes_51 : 48|16@1+ (1,0) [0|65535] ""  MBMU

BO_ 2333605748 S2A_SUMDATA17__52: 8 SBMU
 SG_ S2A_HisOVtimes_52 : 0|16@1+ (1,0) [0|65535] ""  MBMU
 SG_ S2A_HisUVtimes_52 : 16|16@1+ (1,0) [0|65535] ""  MBMU
 SG_ S2A_HisOCCtimes_52 : 32|16@1+ (1,0) [0|65535] ""  MBMU
 SG_ S2A_HisOCDtimes_52 : 48|16@1+ (1,0) [0|65535] ""  MBMU

BO_ 2333605749 S2A_SUMDATA17__53: 8 SBMU
 SG_ S2A_HisOVtimes_53 : 0|16@1+ (1,0) [0|65535] ""  MBMU
 SG_ S2A_HisUVtimes_53 : 16|16@1+ (1,0) [0|65535] ""  MBMU
 SG_ S2A_HisOCCtimes_53 : 32|16@1+ (1,0) [0|65535] ""  MBMU
 SG_ S2A_HisOCDtimes_53 : 48|16@1+ (1,0) [0|65535] ""  MBMU

BO_ 2333605750 S2A_SUMDATA17__54: 8 SBMU
 SG_ S2A_HisOVtimes_54 : 0|16@1+ (1,0) [0|65535] ""  MBMU
 SG_ S2A_HisUVtimes_54 : 16|16@1+ (1,0) [0|65535] ""  MBMU
 SG_ S2A_HisOCCtimes_54 : 32|16@1+ (1,0) [0|65535] ""  MBMU
 SG_ S2A_HisOCDtimes_54 : 48|16@1+ (1,0) [0|65535] ""  MBMU

BO_ 2333605751 S2A_SUMDATA17__55: 8 SBMU
 SG_ S2A_HisOVtimes_55 : 0|16@1+ (1,0) [0|65535] ""  MBMU
 SG_ S2A_HisUVtimes_55 : 16|16@1+ (1,0) [0|65535] ""  MBMU
 SG_ S2A_HisOCCtimes_55 : 32|16@1+ (1,0) [0|65535] ""  MBMU
 SG_ S2A_HisOCDtimes_55 : 48|16@1+ (1,0) [0|65535] ""  MBMU

BO_ 2333605752 S2A_SUMDATA17__56: 8 SBMU
 SG_ S2A_HisOVtimes_56 : 0|16@1+ (1,0) [0|65535] ""  MBMU
 SG_ S2A_HisUVtimes_56 : 16|16@1+ (1,0) [0|65535] ""  MBMU
 SG_ S2A_HisOCCtimes_56 : 32|16@1+ (1,0) [0|65535] ""  MBMU
 SG_ S2A_HisOCDtimes_56 : 48|16@1+ (1,0) [0|65535] ""  MBMU

BO_ 2333605753 S2A_SUMDATA17__57: 8 SBMU
 SG_ S2A_HisOVtimes_57 : 0|16@1+ (1,0) [0|65535] ""  MBMU
 SG_ S2A_HisUVtimes_57 : 16|16@1+ (1,0) [0|65535] ""  MBMU
 SG_ S2A_HisOCCtimes_57 : 32|16@1+ (1,0) [0|65535] ""  MBMU
 SG_ S2A_HisOCDtimes_57 : 48|16@1+ (1,0) [0|65535] ""  MBMU

BO_ 2333605754 S2A_SUMDATA17__58: 8 SBMU
 SG_ S2A_HisOVtimes_58 : 0|16@1+ (1,0) [0|65535] ""  MBMU
 SG_ S2A_HisUVtimes_58 : 16|16@1+ (1,0) [0|65535] ""  MBMU
 SG_ S2A_HisOCCtimes_58 : 32|16@1+ (1,0) [0|65535] ""  MBMU
 SG_ S2A_HisOCDtimes_58 : 48|16@1+ (1,0) [0|65535] ""  MBMU

BO_ 2333605755 S2A_SUMDATA17__59: 8 SBMU
 SG_ S2A_HisOVtimes_59 : 0|16@1+ (1,0) [0|65535] ""  MBMU
 SG_ S2A_HisUVtimes_59 : 16|16@1+ (1,0) [0|65535] ""  MBMU
 SG_ S2A_HisOCCtimes_59 : 32|16@1+ (1,0) [0|65535] ""  MBMU
 SG_ S2A_HisOCDtimes_59 : 48|16@1+ (1,0) [0|65535] ""  MBMU

BO_ 2333605756 S2A_SUMDATA17__60: 8 SBMU
 SG_ S2A_HisOVtimes_60 : 0|16@1+ (1,0) [0|65535] ""  MBMU
 SG_ S2A_HisUVtimes_60 : 16|16@1+ (1,0) [0|65535] ""  MBMU
 SG_ S2A_HisOCCtimes_60 : 32|16@1+ (1,0) [0|65535] ""  MBMU
 SG_ S2A_HisOCDtimes_60 : 48|16@1+ (1,0) [0|65535] ""  MBMU

BO_ 2333605757 S2A_SUMDATA17__61: 8 SBMU
 SG_ S2A_HisOVtimes_61 : 0|16@1+ (1,0) [0|65535] ""  MBMU
 SG_ S2A_HisUVtimes_61 : 16|16@1+ (1,0) [0|65535] ""  MBMU
 SG_ S2A_HisOCCtimes_61 : 32|16@1+ (1,0) [0|65535] ""  MBMU
 SG_ S2A_HisOCDtimes_61 : 48|16@1+ (1,0) [0|65535] ""  MBMU

BO_ 2333605758 S2A_SUMDATA17__62: 8 SBMU
 SG_ S2A_HisOVtimes_62 : 0|16@1+ (1,0) [0|65535] ""  MBMU
 SG_ S2A_HisUVtimes_62 : 16|16@1+ (1,0) [0|65535] ""  MBMU
 SG_ S2A_HisOCCtimes_62 : 32|16@1+ (1,0) [0|65535] ""  MBMU
 SG_ S2A_HisOCDtimes_62 : 48|16@1+ (1,0) [0|65535] ""  MBMU

BO_ 2333605759 S2A_SUMDATA17__63: 8 SBMU
 SG_ S2A_HisOVtimes_63 : 0|16@1+ (1,0) [0|65535] ""  MBMU
 SG_ S2A_HisUVtimes_63 : 16|16@1+ (1,0) [0|65535] ""  MBMU
 SG_ S2A_HisOCCtimes_63 : 32|16@1+ (1,0) [0|65535] ""  MBMU
 SG_ S2A_HisOCDtimes_63 : 48|16@1+ (1,0) [0|65535] ""  MBMU

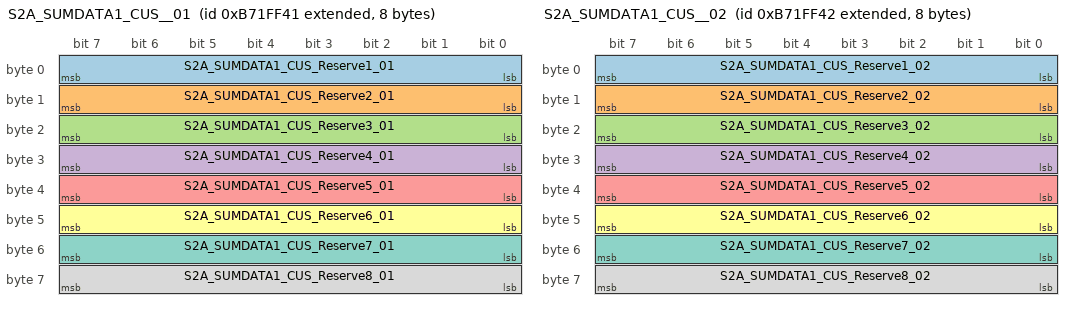
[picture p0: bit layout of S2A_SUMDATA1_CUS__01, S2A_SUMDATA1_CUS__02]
BO_ 2339503937 S2A_SUMDATA1_CUS__01: 8 SBMU
 SG_ S2A_SUMDATA1_CUS_Reserve1_01 : 0|8@1+ (1,0) [0|255] ""  PC,MBMU
 SG_ S2A_SUMDATA1_CUS_Reserve2_01 : 8|8@1+ (1,0) [0|255] ""  PC,MBMU
 SG_ S2A_SUMDATA1_CUS_Reserve3_01 : 16|8@1+ (1,0) [0|255] ""  PC,MBMU
 SG_ S2A_SUMDATA1_CUS_Reserve4_01 : 24|8@1+ (1,0) [0|255] ""  PC,MBMU
 SG_ S2A_SUMDATA1_CUS_Reserve5_01 : 32|8@1+ (1,0) [0|255] ""  PC,MBMU
 SG_ S2A_SUMDATA1_CUS_Reserve6_01 : 40|8@1+ (1,0) [0|255] ""  PC,MBMU
 SG_ S2A_SUMDATA1_CUS_Reserve7_01 : 48|8@1+ (1,0) [0|255] ""  PC,MBMU
 SG_ S2A_SUMDATA1_CUS_Reserve8_01 : 56|8@1+ (1,0) [0|255] ""  PC,MBMU

BO_ 2339503938 S2A_SUMDATA1_CUS__02: 8 SBMU
 SG_ S2A_SUMDATA1_CUS_Reserve1_02 : 0|8@1+ (1,0) [0|255] ""  PC,MBMU
 SG_ S2A_SUMDATA1_CUS_Reserve2_02 : 8|8@1+ (1,0) [0|255] ""  PC,MBMU
 SG_ S2A_SUMDATA1_CUS_Reserve3_02 : 16|8@1+ (1,0) [0|255] ""  PC,MBMU
 SG_ S2A_SUMDATA1_CUS_Reserve4_02 : 24|8@1+ (1,0) [0|255] ""  PC,MBMU
 SG_ S2A_SUMDATA1_CUS_Reserve5_02 : 32|8@1+ (1,0) [0|255] ""  PC,MBMU
 SG_ S2A_SUMDATA1_CUS_Reserve6_02 : 40|8@1+ (1,0) [0|255] ""  PC,MBMU
 SG_ S2A_SUMDATA1_CUS_Reserve7_02 : 48|8@1+ (1,0) [0|255] ""  PC,MBMU
 SG_ S2A_SUMDATA1_CUS_Reserve8_02 : 56|8@1+ (1,0) [0|255] ""  PC,MBMU

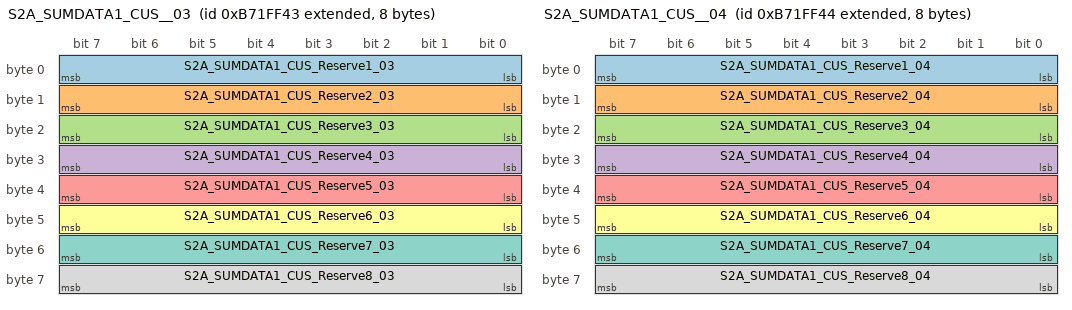
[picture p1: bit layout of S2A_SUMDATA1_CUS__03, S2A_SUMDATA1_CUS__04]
BO_ 2339503939 S2A_SUMDATA1_CUS__03: 8 SBMU
 SG_ S2A_SUMDATA1_CUS_Reserve1_03 : 0|8@1+ (1,0) [0|255] ""  PC,MBMU
 SG_ S2A_SUMDATA1_CUS_Reserve2_03 : 8|8@1+ (1,0) [0|255] ""  PC,MBMU
 SG_ S2A_SUMDATA1_CUS_Reserve3_03 : 16|8@1+ (1,0) [0|255] ""  PC,MBMU
 SG_ S2A_SUMDATA1_CUS_Reserve4_03 : 24|8@1+ (1,0) [0|255] ""  PC,MBMU
 SG_ S2A_SUMDATA1_CUS_Reserve5_03 : 32|8@1+ (1,0) [0|255] ""  PC,MBMU
 SG_ S2A_SUMDATA1_CUS_Reserve6_03 : 40|8@1+ (1,0) [0|255] ""  PC,MBMU
 SG_ S2A_SUMDATA1_CUS_Reserve7_03 : 48|8@1+ (1,0) [0|255] ""  PC,MBMU
 SG_ S2A_SUMDATA1_CUS_Reserve8_03 : 56|8@1+ (1,0) [0|255] ""  PC,MBMU

BO_ 2339503940 S2A_SUMDATA1_CUS__04: 8 SBMU
 SG_ S2A_SUMDATA1_CUS_Reserve1_04 : 0|8@1+ (1,0) [0|255] ""  PC,MBMU
 SG_ S2A_SUMDATA1_CUS_Reserve2_04 : 8|8@1+ (1,0) [0|255] ""  PC,MBMU
 SG_ S2A_SUMDATA1_CUS_Reserve3_04 : 16|8@1+ (1,0) [0|255] ""  PC,MBMU
 SG_ S2A_SUMDATA1_CUS_Reserve4_04 : 24|8@1+ (1,0) [0|255] ""  PC,MBMU
 SG_ S2A_SUMDATA1_CUS_Reserve5_04 : 32|8@1+ (1,0) [0|255] ""  PC,MBMU
 SG_ S2A_SUMDATA1_CUS_Reserve6_04 : 40|8@1+ (1,0) [0|255] ""  PC,MBMU
 SG_ S2A_SUMDATA1_CUS_Reserve7_04 : 48|8@1+ (1,0) [0|255] ""  PC,MBMU
 SG_ S2A_SUMDATA1_CUS_Reserve8_04 : 56|8@1+ (1,0) [0|255] ""  PC,MBMU

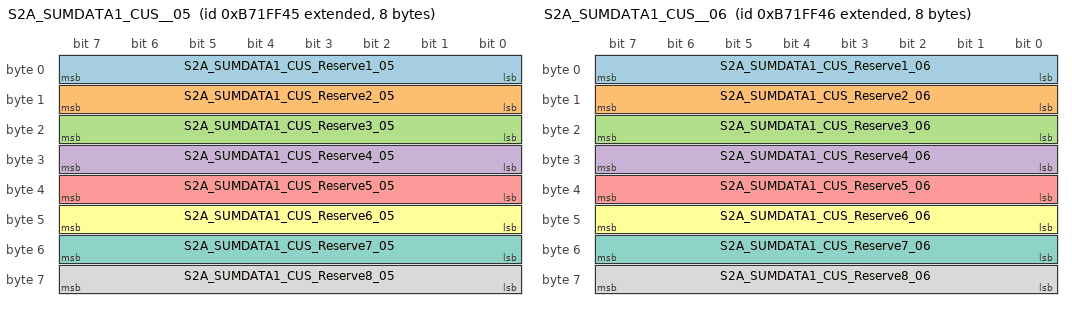
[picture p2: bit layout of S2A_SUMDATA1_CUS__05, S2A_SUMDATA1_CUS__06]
BO_ 2339503941 S2A_SUMDATA1_CUS__05: 8 SBMU
 SG_ S2A_SUMDATA1_CUS_Reserve1_05 : 0|8@1+ (1,0) [0|255] ""  PC,MBMU
 SG_ S2A_SUMDATA1_CUS_Reserve2_05 : 8|8@1+ (1,0) [0|255] ""  PC,MBMU
 SG_ S2A_SUMDATA1_CUS_Reserve3_05 : 16|8@1+ (1,0) [0|255] ""  PC,MBMU
 SG_ S2A_SUMDATA1_CUS_Reserve4_05 : 24|8@1+ (1,0) [0|255] ""  PC,MBMU
 SG_ S2A_SUMDATA1_CUS_Reserve5_05 : 32|8@1+ (1,0) [0|255] ""  PC,MBMU
 SG_ S2A_SUMDATA1_CUS_Reserve6_05 : 40|8@1+ (1,0) [0|255] ""  PC,MBMU
 SG_ S2A_SUMDATA1_CUS_Reserve7_05 : 48|8@1+ (1,0) [0|255] ""  PC,MBMU
 SG_ S2A_SUMDATA1_CUS_Reserve8_05 : 56|8@1+ (1,0) [0|255] ""  PC,MBMU

BO_ 2339503942 S2A_SUMDATA1_CUS__06: 8 SBMU
 SG_ S2A_SUMDATA1_CUS_Reserve1_06 : 0|8@1+ (1,0) [0|255] ""  PC,MBMU
 SG_ S2A_SUMDATA1_CUS_Reserve2_06 : 8|8@1+ (1,0) [0|255] ""  PC,MBMU
 SG_ S2A_SUMDATA1_CUS_Reserve3_06 : 16|8@1+ (1,0) [0|255] ""  PC,MBMU
 SG_ S2A_SUMDATA1_CUS_Reserve4_06 : 24|8@1+ (1,0) [0|255] ""  PC,MBMU
 SG_ S2A_SUMDATA1_CUS_Reserve5_06 : 32|8@1+ (1,0) [0|255] ""  PC,MBMU
 SG_ S2A_SUMDATA1_CUS_Reserve6_06 : 40|8@1+ (1,0) [0|255] ""  PC,MBMU
 SG_ S2A_SUMDATA1_CUS_Reserve7_06 : 48|8@1+ (1,0) [0|255] ""  PC,MBMU
 SG_ S2A_SUMDATA1_CUS_Reserve8_06 : 56|8@1+ (1,0) [0|255] ""  PC,MBMU

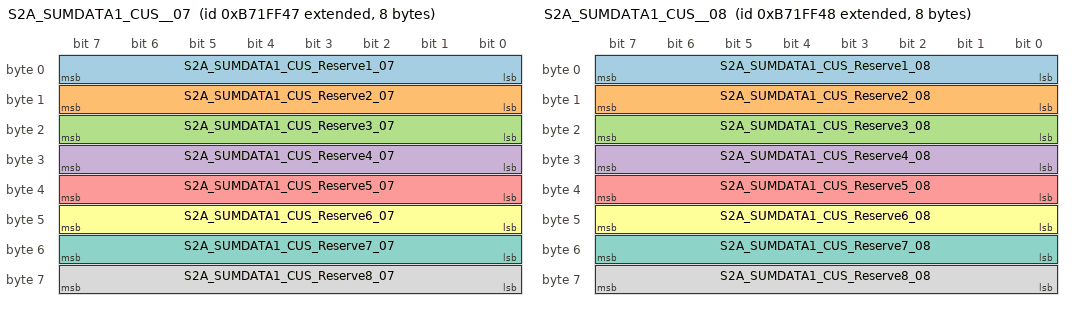
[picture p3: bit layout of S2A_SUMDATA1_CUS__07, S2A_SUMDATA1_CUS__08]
BO_ 2339503943 S2A_SUMDATA1_CUS__07: 8 SBMU
 SG_ S2A_SUMDATA1_CUS_Reserve1_07 : 0|8@1+ (1,0) [0|255] ""  PC,MBMU
 SG_ S2A_SUMDATA1_CUS_Reserve2_07 : 8|8@1+ (1,0) [0|255] ""  PC,MBMU
 SG_ S2A_SUMDATA1_CUS_Reserve3_07 : 16|8@1+ (1,0) [0|255] ""  PC,MBMU
 SG_ S2A_SUMDATA1_CUS_Reserve4_07 : 24|8@1+ (1,0) [0|255] ""  PC,MBMU
 SG_ S2A_SUMDATA1_CUS_Reserve5_07 : 32|8@1+ (1,0) [0|255] ""  PC,MBMU
 SG_ S2A_SUMDATA1_CUS_Reserve6_07 : 40|8@1+ (1,0) [0|255] ""  PC,MBMU
 SG_ S2A_SUMDATA1_CUS_Reserve7_07 : 48|8@1+ (1,0) [0|255] ""  PC,MBMU
 SG_ S2A_SUMDATA1_CUS_Reserve8_07 : 56|8@1+ (1,0) [0|255] ""  PC,MBMU

BO_ 2339503944 S2A_SUMDATA1_CUS__08: 8 SBMU
 SG_ S2A_SUMDATA1_CUS_Reserve1_08 : 0|8@1+ (1,0) [0|255] ""  PC,MBMU
 SG_ S2A_SUMDATA1_CUS_Reserve2_08 : 8|8@1+ (1,0) [0|255] ""  PC,MBMU
 SG_ S2A_SUMDATA1_CUS_Reserve3_08 : 16|8@1+ (1,0) [0|255] ""  PC,MBMU
 SG_ S2A_SUMDATA1_CUS_Reserve4_08 : 24|8@1+ (1,0) [0|255] ""  PC,MBMU
 SG_ S2A_SUMDATA1_CUS_Reserve5_08 : 32|8@1+ (1,0) [0|255] ""  PC,MBMU
 SG_ S2A_SUMDATA1_CUS_Reserve6_08 : 40|8@1+ (1,0) [0|255] ""  PC,MBMU
 SG_ S2A_SUMDATA1_CUS_Reserve7_08 : 48|8@1+ (1,0) [0|255] ""  PC,MBMU
 SG_ S2A_SUMDATA1_CUS_Reserve8_08 : 56|8@1+ (1,0) [0|255] ""  PC,MBMU

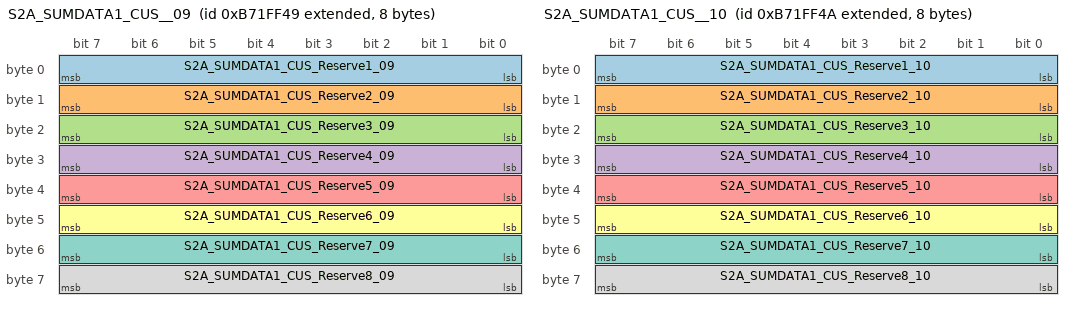
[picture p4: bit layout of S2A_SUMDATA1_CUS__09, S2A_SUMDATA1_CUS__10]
BO_ 2339503945 S2A_SUMDATA1_CUS__09: 8 SBMU
 SG_ S2A_SUMDATA1_CUS_Reserve1_09 : 0|8@1+ (1,0) [0|255] ""  PC,MBMU
 SG_ S2A_SUMDATA1_CUS_Reserve2_09 : 8|8@1+ (1,0) [0|255] ""  PC,MBMU
 SG_ S2A_SUMDATA1_CUS_Reserve3_09 : 16|8@1+ (1,0) [0|255] ""  PC,MBMU
 SG_ S2A_SUMDATA1_CUS_Reserve4_09 : 24|8@1+ (1,0) [0|255] ""  PC,MBMU
 SG_ S2A_SUMDATA1_CUS_Reserve5_09 : 32|8@1+ (1,0) [0|255] ""  PC,MBMU
 SG_ S2A_SUMDATA1_CUS_Reserve6_09 : 40|8@1+ (1,0) [0|255] ""  PC,MBMU
 SG_ S2A_SUMDATA1_CUS_Reserve7_09 : 48|8@1+ (1,0) [0|255] ""  PC,MBMU
 SG_ S2A_SUMDATA1_CUS_Reserve8_09 : 56|8@1+ (1,0) [0|255] ""  PC,MBMU

BO_ 2339503946 S2A_SUMDATA1_CUS__10: 8 SBMU
 SG_ S2A_SUMDATA1_CUS_Reserve1_10 : 0|8@1+ (1,0) [0|255] ""  PC,MBMU
 SG_ S2A_SUMDATA1_CUS_Reserve2_10 : 8|8@1+ (1,0) [0|255] ""  PC,MBMU
 SG_ S2A_SUMDATA1_CUS_Reserve3_10 : 16|8@1+ (1,0) [0|255] ""  PC,MBMU
 SG_ S2A_SUMDATA1_CUS_Reserve4_10 : 24|8@1+ (1,0) [0|255] ""  PC,MBMU
 SG_ S2A_SUMDATA1_CUS_Reserve5_10 : 32|8@1+ (1,0) [0|255] ""  PC,MBMU
 SG_ S2A_SUMDATA1_CUS_Reserve6_10 : 40|8@1+ (1,0) [0|255] ""  PC,MBMU
 SG_ S2A_SUMDATA1_CUS_Reserve7_10 : 48|8@1+ (1,0) [0|255] ""  PC,MBMU
 SG_ S2A_SUMDATA1_CUS_Reserve8_10 : 56|8@1+ (1,0) [0|255] ""  PC,MBMU

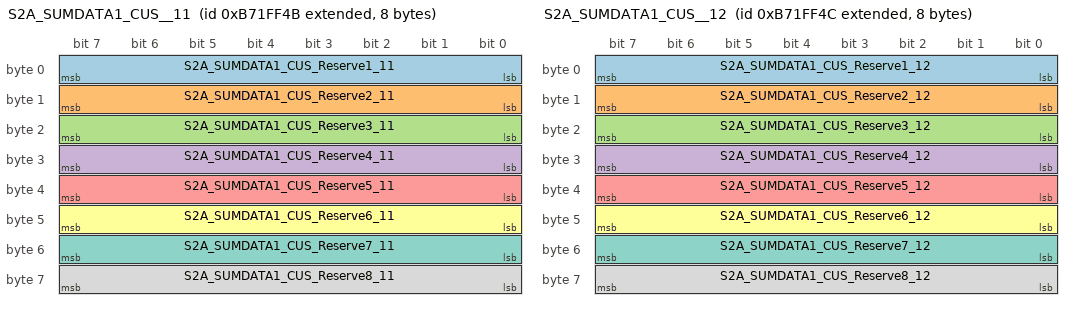
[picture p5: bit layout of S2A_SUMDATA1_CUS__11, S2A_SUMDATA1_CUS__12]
BO_ 2339503947 S2A_SUMDATA1_CUS__11: 8 SBMU
 SG_ S2A_SUMDATA1_CUS_Reserve1_11 : 0|8@1+ (1,0) [0|255] ""  PC,MBMU
 SG_ S2A_SUMDATA1_CUS_Reserve2_11 : 8|8@1+ (1,0) [0|255] ""  PC,MBMU
 SG_ S2A_SUMDATA1_CUS_Reserve3_11 : 16|8@1+ (1,0) [0|255] ""  PC,MBMU
 SG_ S2A_SUMDATA1_CUS_Reserve4_11 : 24|8@1+ (1,0) [0|255] ""  PC,MBMU
 SG_ S2A_SUMDATA1_CUS_Reserve5_11 : 32|8@1+ (1,0) [0|255] ""  PC,MBMU
 SG_ S2A_SUMDATA1_CUS_Reserve6_11 : 40|8@1+ (1,0) [0|255] ""  PC,MBMU
 SG_ S2A_SUMDATA1_CUS_Reserve7_11 : 48|8@1+ (1,0) [0|255] ""  PC,MBMU
 SG_ S2A_SUMDATA1_CUS_Reserve8_11 : 56|8@1+ (1,0) [0|255] ""  PC,MBMU

BO_ 2339503948 S2A_SUMDATA1_CUS__12: 8 SBMU
 SG_ S2A_SUMDATA1_CUS_Reserve1_12 : 0|8@1+ (1,0) [0|255] ""  PC,MBMU
 SG_ S2A_SUMDATA1_CUS_Reserve2_12 : 8|8@1+ (1,0) [0|255] ""  PC,MBMU
 SG_ S2A_SUMDATA1_CUS_Reserve3_12 : 16|8@1+ (1,0) [0|255] ""  PC,MBMU
 SG_ S2A_SUMDATA1_CUS_Reserve4_12 : 24|8@1+ (1,0) [0|255] ""  PC,MBMU
 SG_ S2A_SUMDATA1_CUS_Reserve5_12 : 32|8@1+ (1,0) [0|255] ""  PC,MBMU
 SG_ S2A_SUMDATA1_CUS_Reserve6_12 : 40|8@1+ (1,0) [0|255] ""  PC,MBMU
 SG_ S2A_SUMDATA1_CUS_Reserve7_12 : 48|8@1+ (1,0) [0|255] ""  PC,MBMU
 SG_ S2A_SUMDATA1_CUS_Reserve8_12 : 56|8@1+ (1,0) [0|255] ""  PC,MBMU

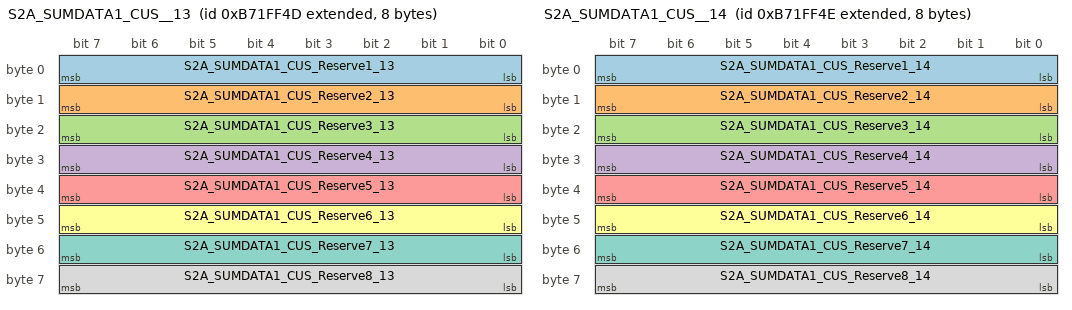
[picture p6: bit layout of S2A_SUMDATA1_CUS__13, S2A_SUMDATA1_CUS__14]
BO_ 2339503949 S2A_SUMDATA1_CUS__13: 8 SBMU
 SG_ S2A_SUMDATA1_CUS_Reserve1_13 : 0|8@1+ (1,0) [0|255] ""  PC,MBMU
 SG_ S2A_SUMDATA1_CUS_Reserve2_13 : 8|8@1+ (1,0) [0|255] ""  PC,MBMU
 SG_ S2A_SUMDATA1_CUS_Reserve3_13 : 16|8@1+ (1,0) [0|255] ""  PC,MBMU
 SG_ S2A_SUMDATA1_CUS_Reserve4_13 : 24|8@1+ (1,0) [0|255] ""  PC,MBMU
 SG_ S2A_SUMDATA1_CUS_Reserve5_13 : 32|8@1+ (1,0) [0|255] ""  PC,MBMU
 SG_ S2A_SUMDATA1_CUS_Reserve6_13 : 40|8@1+ (1,0) [0|255] ""  PC,MBMU
 SG_ S2A_SUMDATA1_CUS_Reserve7_13 : 48|8@1+ (1,0) [0|255] ""  PC,MBMU
 SG_ S2A_SUMDATA1_CUS_Reserve8_13 : 56|8@1+ (1,0) [0|255] ""  PC,MBMU

BO_ 2339503950 S2A_SUMDATA1_CUS__14: 8 SBMU
 SG_ S2A_SUMDATA1_CUS_Reserve1_14 : 0|8@1+ (1,0) [0|255] ""  PC,MBMU
 SG_ S2A_SUMDATA1_CUS_Reserve2_14 : 8|8@1+ (1,0) [0|255] ""  PC,MBMU
 SG_ S2A_SUMDATA1_CUS_Reserve3_14 : 16|8@1+ (1,0) [0|255] ""  PC,MBMU
 SG_ S2A_SUMDATA1_CUS_Reserve4_14 : 24|8@1+ (1,0) [0|255] ""  PC,MBMU
 SG_ S2A_SUMDATA1_CUS_Reserve5_14 : 32|8@1+ (1,0) [0|255] ""  PC,MBMU
 SG_ S2A_SUMDATA1_CUS_Reserve6_14 : 40|8@1+ (1,0) [0|255] ""  PC,MBMU
 SG_ S2A_SUMDATA1_CUS_Reserve7_14 : 48|8@1+ (1,0) [0|255] ""  PC,MBMU
 SG_ S2A_SUMDATA1_CUS_Reserve8_14 : 56|8@1+ (1,0) [0|255] ""  PC,MBMU

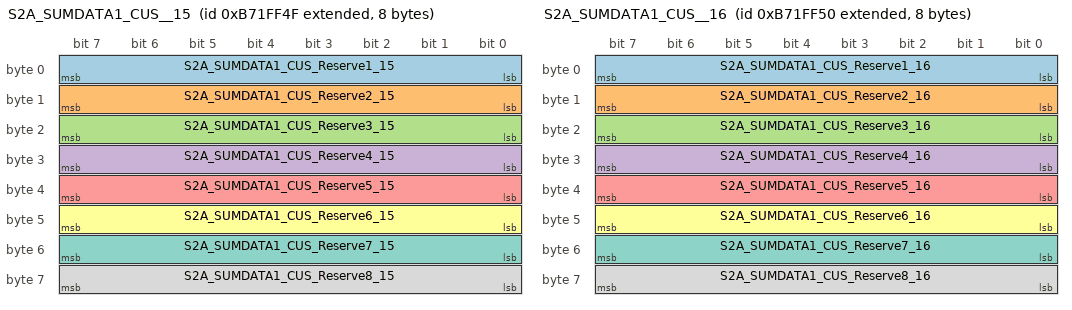
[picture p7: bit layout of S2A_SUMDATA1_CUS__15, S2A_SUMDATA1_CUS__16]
BO_ 2339503951 S2A_SUMDATA1_CUS__15: 8 SBMU
 SG_ S2A_SUMDATA1_CUS_Reserve1_15 : 0|8@1+ (1,0) [0|255] ""  PC,MBMU
 SG_ S2A_SUMDATA1_CUS_Reserve2_15 : 8|8@1+ (1,0) [0|255] ""  PC,MBMU
 SG_ S2A_SUMDATA1_CUS_Reserve3_15 : 16|8@1+ (1,0) [0|255] ""  PC,MBMU
 SG_ S2A_SUMDATA1_CUS_Reserve4_15 : 24|8@1+ (1,0) [0|255] ""  PC,MBMU
 SG_ S2A_SUMDATA1_CUS_Reserve5_15 : 32|8@1+ (1,0) [0|255] ""  PC,MBMU
 SG_ S2A_SUMDATA1_CUS_Reserve6_15 : 40|8@1+ (1,0) [0|255] ""  PC,MBMU
 SG_ S2A_SUMDATA1_CUS_Reserve7_15 : 48|8@1+ (1,0) [0|255] ""  PC,MBMU
 SG_ S2A_SUMDATA1_CUS_Reserve8_15 : 56|8@1+ (1,0) [0|255] ""  PC,MBMU

BO_ 2339503952 S2A_SUMDATA1_CUS__16: 8 SBMU
 SG_ S2A_SUMDATA1_CUS_Reserve1_16 : 0|8@1+ (1,0) [0|255] ""  PC,MBMU
 SG_ S2A_SUMDATA1_CUS_Reserve2_16 : 8|8@1+ (1,0) [0|255] ""  PC,MBMU
 SG_ S2A_SUMDATA1_CUS_Reserve3_16 : 16|8@1+ (1,0) [0|255] ""  PC,MBMU
 SG_ S2A_SUMDATA1_CUS_Reserve4_16 : 24|8@1+ (1,0) [0|255] ""  PC,MBMU
 SG_ S2A_SUMDATA1_CUS_Reserve5_16 : 32|8@1+ (1,0) [0|255] ""  PC,MBMU
 SG_ S2A_SUMDATA1_CUS_Reserve6_16 : 40|8@1+ (1,0) [0|255] ""  PC,MBMU
 SG_ S2A_SUMDATA1_CUS_Reserve7_16 : 48|8@1+ (1,0) [0|255] ""  PC,MBMU
 SG_ S2A_SUMDATA1_CUS_Reserve8_16 : 56|8@1+ (1,0) [0|255] ""  PC,MBMU

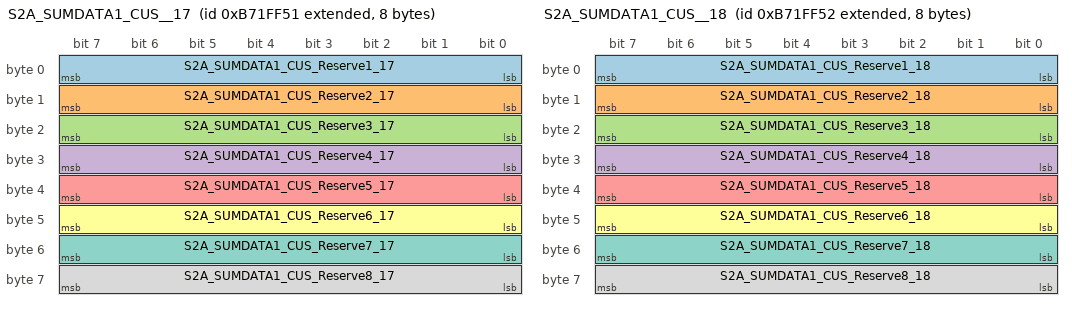
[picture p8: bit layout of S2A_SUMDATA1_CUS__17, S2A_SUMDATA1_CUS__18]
BO_ 2339503953 S2A_SUMDATA1_CUS__17: 8 SBMU
 SG_ S2A_SUMDATA1_CUS_Reserve1_17 : 0|8@1+ (1,0) [0|255] ""  PC,MBMU
 SG_ S2A_SUMDATA1_CUS_Reserve2_17 : 8|8@1+ (1,0) [0|255] ""  PC,MBMU
 SG_ S2A_SUMDATA1_CUS_Reserve3_17 : 16|8@1+ (1,0) [0|255] ""  PC,MBMU
 SG_ S2A_SUMDATA1_CUS_Reserve4_17 : 24|8@1+ (1,0) [0|255] ""  PC,MBMU
 SG_ S2A_SUMDATA1_CUS_Reserve5_17 : 32|8@1+ (1,0) [0|255] ""  PC,MBMU
 SG_ S2A_SUMDATA1_CUS_Reserve6_17 : 40|8@1+ (1,0) [0|255] ""  PC,MBMU
 SG_ S2A_SUMDATA1_CUS_Reserve7_17 : 48|8@1+ (1,0) [0|255] ""  PC,MBMU
 SG_ S2A_SUMDATA1_CUS_Reserve8_17 : 56|8@1+ (1,0) [0|255] ""  PC,MBMU

BO_ 2339503954 S2A_SUMDATA1_CUS__18: 8 SBMU
 SG_ S2A_SUMDATA1_CUS_Reserve1_18 : 0|8@1+ (1,0) [0|255] ""  PC,MBMU
 SG_ S2A_SUMDATA1_CUS_Reserve2_18 : 8|8@1+ (1,0) [0|255] ""  PC,MBMU
 SG_ S2A_SUMDATA1_CUS_Reserve3_18 : 16|8@1+ (1,0) [0|255] ""  PC,MBMU
 SG_ S2A_SUMDATA1_CUS_Reserve4_18 : 24|8@1+ (1,0) [0|255] ""  PC,MBMU
 SG_ S2A_SUMDATA1_CUS_Reserve5_18 : 32|8@1+ (1,0) [0|255] ""  PC,MBMU
 SG_ S2A_SUMDATA1_CUS_Reserve6_18 : 40|8@1+ (1,0) [0|255] ""  PC,MBMU
 SG_ S2A_SUMDATA1_CUS_Reserve7_18 : 48|8@1+ (1,0) [0|255] ""  PC,MBMU
 SG_ S2A_SUMDATA1_CUS_Reserve8_18 : 56|8@1+ (1,0) [0|255] ""  PC,MBMU

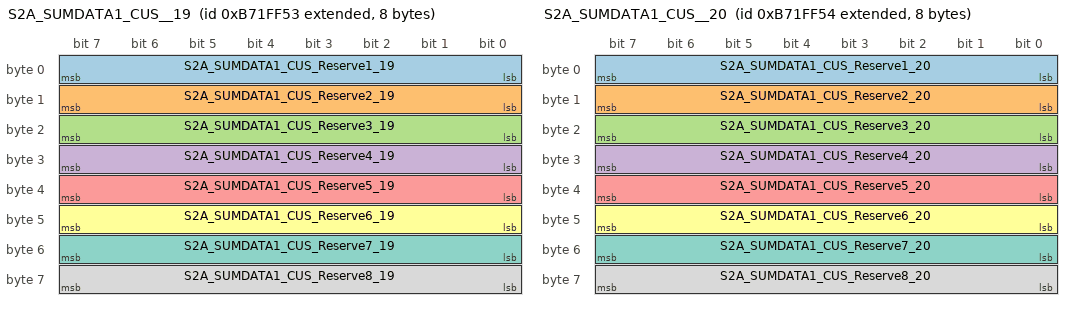
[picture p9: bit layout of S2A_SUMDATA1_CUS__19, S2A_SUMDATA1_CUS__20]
BO_ 2339503955 S2A_SUMDATA1_CUS__19: 8 SBMU
 SG_ S2A_SUMDATA1_CUS_Reserve1_19 : 0|8@1+ (1,0) [0|255] ""  PC,MBMU
 SG_ S2A_SUMDATA1_CUS_Reserve2_19 : 8|8@1+ (1,0) [0|255] ""  PC,MBMU
 SG_ S2A_SUMDATA1_CUS_Reserve3_19 : 16|8@1+ (1,0) [0|255] ""  PC,MBMU
 SG_ S2A_SUMDATA1_CUS_Reserve4_19 : 24|8@1+ (1,0) [0|255] ""  PC,MBMU
 SG_ S2A_SUMDATA1_CUS_Reserve5_19 : 32|8@1+ (1,0) [0|255] ""  PC,MBMU
 SG_ S2A_SUMDATA1_CUS_Reserve6_19 : 40|8@1+ (1,0) [0|255] ""  PC,MBMU
 SG_ S2A_SUMDATA1_CUS_Reserve7_19 : 48|8@1+ (1,0) [0|255] ""  PC,MBMU
 SG_ S2A_SUMDATA1_CUS_Reserve8_19 : 56|8@1+ (1,0) [0|255] ""  PC,MBMU

BO_ 2339503956 S2A_SUMDATA1_CUS__20: 8 SBMU
 SG_ S2A_SUMDATA1_CUS_Reserve1_20 : 0|8@1+ (1,0) [0|255] ""  PC,MBMU
 SG_ S2A_SUMDATA1_CUS_Reserve2_20 : 8|8@1+ (1,0) [0|255] ""  PC,MBMU
 SG_ S2A_SUMDATA1_CUS_Reserve3_20 : 16|8@1+ (1,0) [0|255] ""  PC,MBMU
 SG_ S2A_SUMDATA1_CUS_Reserve4_20 : 24|8@1+ (1,0) [0|255] ""  PC,MBMU
 SG_ S2A_SUMDATA1_CUS_Reserve5_20 : 32|8@1+ (1,0) [0|255] ""  PC,MBMU
 SG_ S2A_SUMDATA1_CUS_Reserve6_20 : 40|8@1+ (1,0) [0|255] ""  PC,MBMU
 SG_ S2A_SUMDATA1_CUS_Reserve7_20 : 48|8@1+ (1,0) [0|255] ""  PC,MBMU
 SG_ S2A_SUMDATA1_CUS_Reserve8_20 : 56|8@1+ (1,0) [0|255] ""  PC,MBMU

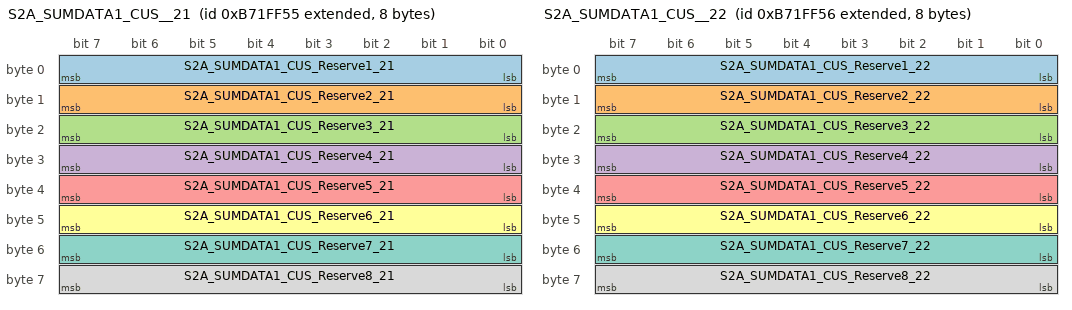
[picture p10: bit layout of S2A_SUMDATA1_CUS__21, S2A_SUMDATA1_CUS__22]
BO_ 2339503957 S2A_SUMDATA1_CUS__21: 8 SBMU
 SG_ S2A_SUMDATA1_CUS_Reserve1_21 : 0|8@1+ (1,0) [0|255] ""  PC,MBMU
 SG_ S2A_SUMDATA1_CUS_Reserve2_21 : 8|8@1+ (1,0) [0|255] ""  PC,MBMU
 SG_ S2A_SUMDATA1_CUS_Reserve3_21 : 16|8@1+ (1,0) [0|255] ""  PC,MBMU
 SG_ S2A_SUMDATA1_CUS_Reserve4_21 : 24|8@1+ (1,0) [0|255] ""  PC,MBMU
 SG_ S2A_SUMDATA1_CUS_Reserve5_21 : 32|8@1+ (1,0) [0|255] ""  PC,MBMU
 SG_ S2A_SUMDATA1_CUS_Reserve6_21 : 40|8@1+ (1,0) [0|255] ""  PC,MBMU
 SG_ S2A_SUMDATA1_CUS_Reserve7_21 : 48|8@1+ (1,0) [0|255] ""  PC,MBMU
 SG_ S2A_SUMDATA1_CUS_Reserve8_21 : 56|8@1+ (1,0) [0|255] ""  PC,MBMU

BO_ 2339503958 S2A_SUMDATA1_CUS__22: 8 SBMU
 SG_ S2A_SUMDATA1_CUS_Reserve1_22 : 0|8@1+ (1,0) [0|255] ""  PC,MBMU
 SG_ S2A_SUMDATA1_CUS_Reserve2_22 : 8|8@1+ (1,0) [0|255] ""  PC,MBMU
 SG_ S2A_SUMDATA1_CUS_Reserve3_22 : 16|8@1+ (1,0) [0|255] ""  PC,MBMU
 SG_ S2A_SUMDATA1_CUS_Reserve4_22 : 24|8@1+ (1,0) [0|255] ""  PC,MBMU
 SG_ S2A_SUMDATA1_CUS_Reserve5_22 : 32|8@1+ (1,0) [0|255] ""  PC,MBMU
 SG_ S2A_SUMDATA1_CUS_Reserve6_22 : 40|8@1+ (1,0) [0|255] ""  PC,MBMU
 SG_ S2A_SUMDATA1_CUS_Reserve7_22 : 48|8@1+ (1,0) [0|255] ""  PC,MBMU
 SG_ S2A_SUMDATA1_CUS_Reserve8_22 : 56|8@1+ (1,0) [0|255] ""  PC,MBMU

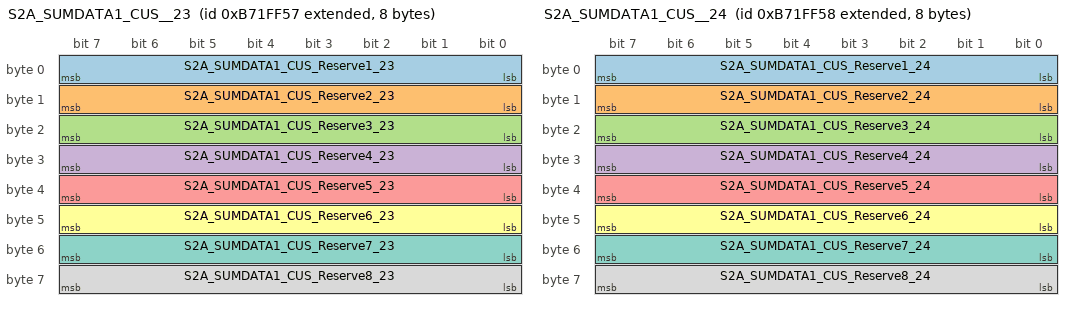
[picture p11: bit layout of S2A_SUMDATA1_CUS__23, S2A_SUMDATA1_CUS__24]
BO_ 2339503959 S2A_SUMDATA1_CUS__23: 8 SBMU
 SG_ S2A_SUMDATA1_CUS_Reserve1_23 : 0|8@1+ (1,0) [0|255] ""  PC,MBMU
 SG_ S2A_SUMDATA1_CUS_Reserve2_23 : 8|8@1+ (1,0) [0|255] ""  PC,MBMU
 SG_ S2A_SUMDATA1_CUS_Reserve3_23 : 16|8@1+ (1,0) [0|255] ""  PC,MBMU
 SG_ S2A_SUMDATA1_CUS_Reserve4_23 : 24|8@1+ (1,0) [0|255] ""  PC,MBMU
 SG_ S2A_SUMDATA1_CUS_Reserve5_23 : 32|8@1+ (1,0) [0|255] ""  PC,MBMU
 SG_ S2A_SUMDATA1_CUS_Reserve6_23 : 40|8@1+ (1,0) [0|255] ""  PC,MBMU
 SG_ S2A_SUMDATA1_CUS_Reserve7_23 : 48|8@1+ (1,0) [0|255] ""  PC,MBMU
 SG_ S2A_SUMDATA1_CUS_Reserve8_23 : 56|8@1+ (1,0) [0|255] ""  PC,MBMU

BO_ 2339503960 S2A_SUMDATA1_CUS__24: 8 SBMU
 SG_ S2A_SUMDATA1_CUS_Reserve1_24 : 0|8@1+ (1,0) [0|255] ""  PC,MBMU
 SG_ S2A_SUMDATA1_CUS_Reserve2_24 : 8|8@1+ (1,0) [0|255] ""  PC,MBMU
 SG_ S2A_SUMDATA1_CUS_Reserve3_24 : 16|8@1+ (1,0) [0|255] ""  PC,MBMU
 SG_ S2A_SUMDATA1_CUS_Reserve4_24 : 24|8@1+ (1,0) [0|255] ""  PC,MBMU
 SG_ S2A_SUMDATA1_CUS_Reserve5_24 : 32|8@1+ (1,0) [0|255] ""  PC,MBMU
 SG_ S2A_SUMDATA1_CUS_Reserve6_24 : 40|8@1+ (1,0) [0|255] ""  PC,MBMU
 SG_ S2A_SUMDATA1_CUS_Reserve7_24 : 48|8@1+ (1,0) [0|255] ""  PC,MBMU
 SG_ S2A_SUMDATA1_CUS_Reserve8_24 : 56|8@1+ (1,0) [0|255] ""  PC,MBMU

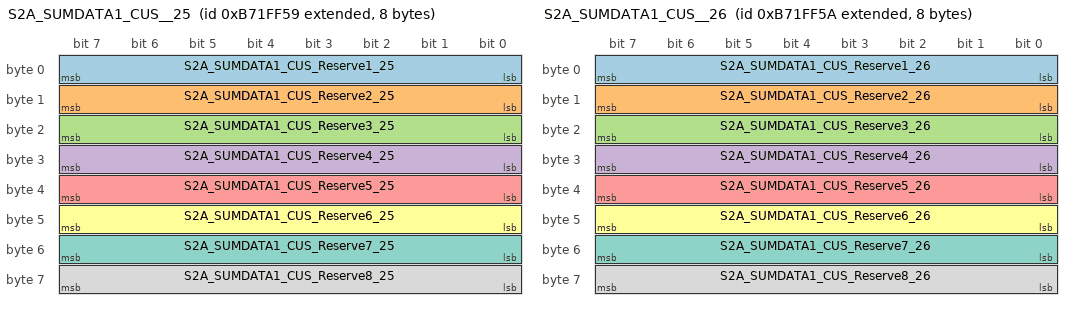
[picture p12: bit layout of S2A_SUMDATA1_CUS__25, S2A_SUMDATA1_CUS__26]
BO_ 2339503961 S2A_SUMDATA1_CUS__25: 8 SBMU
 SG_ S2A_SUMDATA1_CUS_Reserve1_25 : 0|8@1+ (1,0) [0|255] ""  PC,MBMU
 SG_ S2A_SUMDATA1_CUS_Reserve2_25 : 8|8@1+ (1,0) [0|255] ""  PC,MBMU
 SG_ S2A_SUMDATA1_CUS_Reserve3_25 : 16|8@1+ (1,0) [0|255] ""  PC,MBMU
 SG_ S2A_SUMDATA1_CUS_Reserve4_25 : 24|8@1+ (1,0) [0|255] ""  PC,MBMU
 SG_ S2A_SUMDATA1_CUS_Reserve5_25 : 32|8@1+ (1,0) [0|255] ""  PC,MBMU
 SG_ S2A_SUMDATA1_CUS_Reserve6_25 : 40|8@1+ (1,0) [0|255] ""  PC,MBMU
 SG_ S2A_SUMDATA1_CUS_Reserve7_25 : 48|8@1+ (1,0) [0|255] ""  PC,MBMU
 SG_ S2A_SUMDATA1_CUS_Reserve8_25 : 56|8@1+ (1,0) [0|255] ""  PC,MBMU

BO_ 2339503962 S2A_SUMDATA1_CUS__26: 8 SBMU
 SG_ S2A_SUMDATA1_CUS_Reserve1_26 : 0|8@1+ (1,0) [0|255] ""  PC,MBMU
 SG_ S2A_SUMDATA1_CUS_Reserve2_26 : 8|8@1+ (1,0) [0|255] ""  PC,MBMU
 SG_ S2A_SUMDATA1_CUS_Reserve3_26 : 16|8@1+ (1,0) [0|255] ""  PC,MBMU
 SG_ S2A_SUMDATA1_CUS_Reserve4_26 : 24|8@1+ (1,0) [0|255] ""  PC,MBMU
 SG_ S2A_SUMDATA1_CUS_Reserve5_26 : 32|8@1+ (1,0) [0|255] ""  PC,MBMU
 SG_ S2A_SUMDATA1_CUS_Reserve6_26 : 40|8@1+ (1,0) [0|255] ""  PC,MBMU
 SG_ S2A_SUMDATA1_CUS_Reserve7_26 : 48|8@1+ (1,0) [0|255] ""  PC,MBMU
 SG_ S2A_SUMDATA1_CUS_Reserve8_26 : 56|8@1+ (1,0) [0|255] ""  PC,MBMU

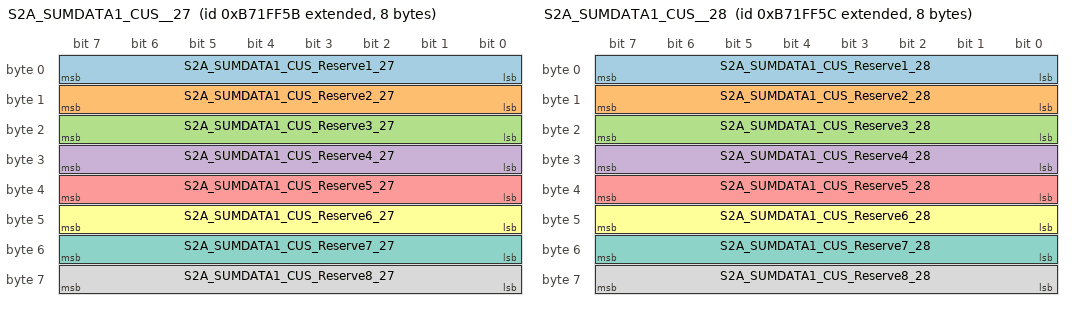
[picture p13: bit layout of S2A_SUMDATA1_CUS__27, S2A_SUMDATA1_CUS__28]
BO_ 2339503963 S2A_SUMDATA1_CUS__27: 8 SBMU
 SG_ S2A_SUMDATA1_CUS_Reserve1_27 : 0|8@1+ (1,0) [0|255] ""  PC,MBMU
 SG_ S2A_SUMDATA1_CUS_Reserve2_27 : 8|8@1+ (1,0) [0|255] ""  PC,MBMU
 SG_ S2A_SUMDATA1_CUS_Reserve3_27 : 16|8@1+ (1,0) [0|255] ""  PC,MBMU
 SG_ S2A_SUMDATA1_CUS_Reserve4_27 : 24|8@1+ (1,0) [0|255] ""  PC,MBMU
 SG_ S2A_SUMDATA1_CUS_Reserve5_27 : 32|8@1+ (1,0) [0|255] ""  PC,MBMU
 SG_ S2A_SUMDATA1_CUS_Reserve6_27 : 40|8@1+ (1,0) [0|255] ""  PC,MBMU
 SG_ S2A_SUMDATA1_CUS_Reserve7_27 : 48|8@1+ (1,0) [0|255] ""  PC,MBMU
 SG_ S2A_SUMDATA1_CUS_Reserve8_27 : 56|8@1+ (1,0) [0|255] ""  PC,MBMU

BO_ 2339503964 S2A_SUMDATA1_CUS__28: 8 SBMU
 SG_ S2A_SUMDATA1_CUS_Reserve1_28 : 0|8@1+ (1,0) [0|255] ""  PC,MBMU
 SG_ S2A_SUMDATA1_CUS_Reserve2_28 : 8|8@1+ (1,0) [0|255] ""  PC,MBMU
 SG_ S2A_SUMDATA1_CUS_Reserve3_28 : 16|8@1+ (1,0) [0|255] ""  PC,MBMU
 SG_ S2A_SUMDATA1_CUS_Reserve4_28 : 24|8@1+ (1,0) [0|255] ""  PC,MBMU
 SG_ S2A_SUMDATA1_CUS_Reserve5_28 : 32|8@1+ (1,0) [0|255] ""  PC,MBMU
 SG_ S2A_SUMDATA1_CUS_Reserve6_28 : 40|8@1+ (1,0) [0|255] ""  PC,MBMU
 SG_ S2A_SUMDATA1_CUS_Reserve7_28 : 48|8@1+ (1,0) [0|255] ""  PC,MBMU
 SG_ S2A_SUMDATA1_CUS_Reserve8_28 : 56|8@1+ (1,0) [0|255] ""  PC,MBMU

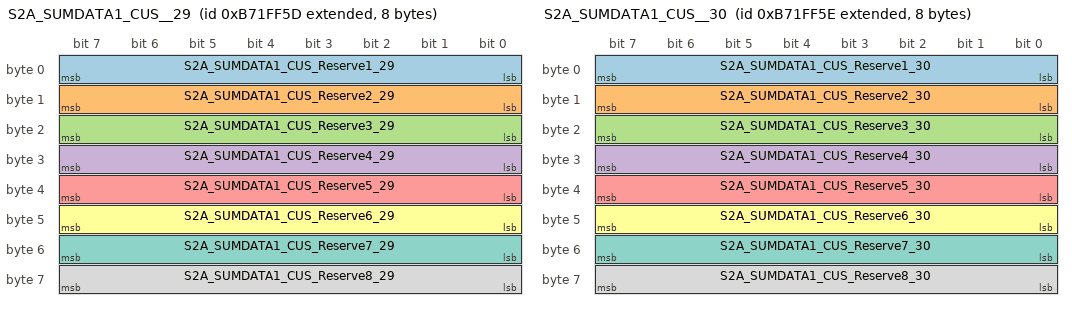
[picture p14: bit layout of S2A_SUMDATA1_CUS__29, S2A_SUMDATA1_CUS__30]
BO_ 2339503965 S2A_SUMDATA1_CUS__29: 8 SBMU
 SG_ S2A_SUMDATA1_CUS_Reserve1_29 : 0|8@1+ (1,0) [0|255] ""  PC,MBMU
 SG_ S2A_SUMDATA1_CUS_Reserve2_29 : 8|8@1+ (1,0) [0|255] ""  PC,MBMU
 SG_ S2A_SUMDATA1_CUS_Reserve3_29 : 16|8@1+ (1,0) [0|255] ""  PC,MBMU
 SG_ S2A_SUMDATA1_CUS_Reserve4_29 : 24|8@1+ (1,0) [0|255] ""  PC,MBMU
 SG_ S2A_SUMDATA1_CUS_Reserve5_29 : 32|8@1+ (1,0) [0|255] ""  PC,MBMU
 SG_ S2A_SUMDATA1_CUS_Reserve6_29 : 40|8@1+ (1,0) [0|255] ""  PC,MBMU
 SG_ S2A_SUMDATA1_CUS_Reserve7_29 : 48|8@1+ (1,0) [0|255] ""  PC,MBMU
 SG_ S2A_SUMDATA1_CUS_Reserve8_29 : 56|8@1+ (1,0) [0|255] ""  PC,MBMU

BO_ 2339503966 S2A_SUMDATA1_CUS__30: 8 SBMU
 SG_ S2A_SUMDATA1_CUS_Reserve1_30 : 0|8@1+ (1,0) [0|255] ""  PC,MBMU
 SG_ S2A_SUMDATA1_CUS_Reserve2_30 : 8|8@1+ (1,0) [0|255] ""  PC,MBMU
 SG_ S2A_SUMDATA1_CUS_Reserve3_30 : 16|8@1+ (1,0) [0|255] ""  PC,MBMU
 SG_ S2A_SUMDATA1_CUS_Reserve4_30 : 24|8@1+ (1,0) [0|255] ""  PC,MBMU
 SG_ S2A_SUMDATA1_CUS_Reserve5_30 : 32|8@1+ (1,0) [0|255] ""  PC,MBMU
 SG_ S2A_SUMDATA1_CUS_Reserve6_30 : 40|8@1+ (1,0) [0|255] ""  PC,MBMU
 SG_ S2A_SUMDATA1_CUS_Reserve7_30 : 48|8@1+ (1,0) [0|255] ""  PC,MBMU
 SG_ S2A_SUMDATA1_CUS_Reserve8_30 : 56|8@1+ (1,0) [0|255] ""  PC,MBMU

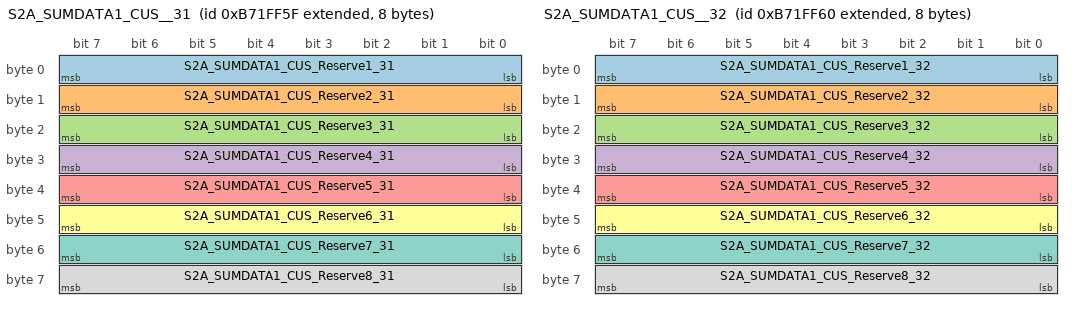
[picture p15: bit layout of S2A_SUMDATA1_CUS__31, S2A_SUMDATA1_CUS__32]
BO_ 2339503967 S2A_SUMDATA1_CUS__31: 8 SBMU
 SG_ S2A_SUMDATA1_CUS_Reserve1_31 : 0|8@1+ (1,0) [0|255] ""  PC,MBMU
 SG_ S2A_SUMDATA1_CUS_Reserve2_31 : 8|8@1+ (1,0) [0|255] ""  PC,MBMU
 SG_ S2A_SUMDATA1_CUS_Reserve3_31 : 16|8@1+ (1,0) [0|255] ""  PC,MBMU
 SG_ S2A_SUMDATA1_CUS_Reserve4_31 : 24|8@1+ (1,0) [0|255] ""  PC,MBMU
 SG_ S2A_SUMDATA1_CUS_Reserve5_31 : 32|8@1+ (1,0) [0|255] ""  PC,MBMU
 SG_ S2A_SUMDATA1_CUS_Reserve6_31 : 40|8@1+ (1,0) [0|255] ""  PC,MBMU
 SG_ S2A_SUMDATA1_CUS_Reserve7_31 : 48|8@1+ (1,0) [0|255] ""  PC,MBMU
 SG_ S2A_SUMDATA1_CUS_Reserve8_31 : 56|8@1+ (1,0) [0|255] ""  PC,MBMU

BO_ 2339503968 S2A_SUMDATA1_CUS__32: 8 SBMU
 SG_ S2A_SUMDATA1_CUS_Reserve1_32 : 0|8@1+ (1,0) [0|255] ""  PC,MBMU
 SG_ S2A_SUMDATA1_CUS_Reserve2_32 : 8|8@1+ (1,0) [0|255] ""  PC,MBMU
 SG_ S2A_SUMDATA1_CUS_Reserve3_32 : 16|8@1+ (1,0) [0|255] ""  PC,MBMU
 SG_ S2A_SUMDATA1_CUS_Reserve4_32 : 24|8@1+ (1,0) [0|255] ""  PC,MBMU
 SG_ S2A_SUMDATA1_CUS_Reserve5_32 : 32|8@1+ (1,0) [0|255] ""  PC,MBMU
 SG_ S2A_SUMDATA1_CUS_Reserve6_32 : 40|8@1+ (1,0) [0|255] ""  PC,MBMU
 SG_ S2A_SUMDATA1_CUS_Reserve7_32 : 48|8@1+ (1,0) [0|255] ""  PC,MBMU
 SG_ S2A_SUMDATA1_CUS_Reserve8_32 : 56|8@1+ (1,0) [0|255] ""  PC,MBMU

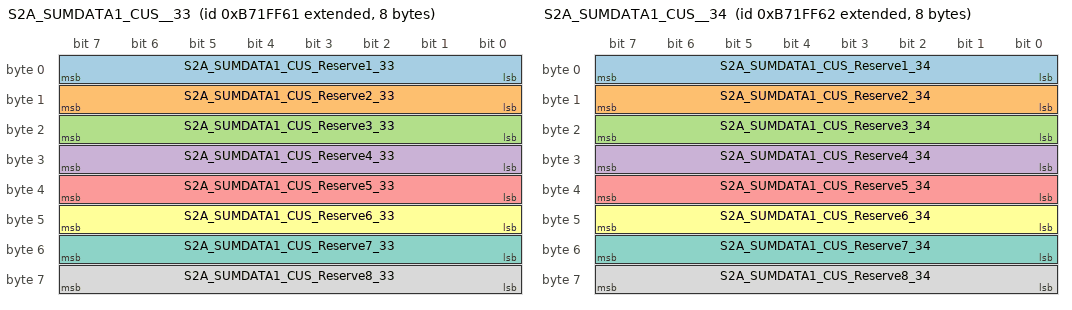
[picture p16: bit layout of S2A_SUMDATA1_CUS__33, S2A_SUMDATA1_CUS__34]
BO_ 2339503969 S2A_SUMDATA1_CUS__33: 8 SBMU
 SG_ S2A_SUMDATA1_CUS_Reserve1_33 : 0|8@1+ (1,0) [0|255] ""  PC,MBMU
 SG_ S2A_SUMDATA1_CUS_Reserve2_33 : 8|8@1+ (1,0) [0|255] ""  PC,MBMU
 SG_ S2A_SUMDATA1_CUS_Reserve3_33 : 16|8@1+ (1,0) [0|255] ""  PC,MBMU
 SG_ S2A_SUMDATA1_CUS_Reserve4_33 : 24|8@1+ (1,0) [0|255] ""  PC,MBMU
 SG_ S2A_SUMDATA1_CUS_Reserve5_33 : 32|8@1+ (1,0) [0|255] ""  PC,MBMU
 SG_ S2A_SUMDATA1_CUS_Reserve6_33 : 40|8@1+ (1,0) [0|255] ""  PC,MBMU
 SG_ S2A_SUMDATA1_CUS_Reserve7_33 : 48|8@1+ (1,0) [0|255] ""  PC,MBMU
 SG_ S2A_SUMDATA1_CUS_Reserve8_33 : 56|8@1+ (1,0) [0|255] ""  PC,MBMU

BO_ 2339503970 S2A_SUMDATA1_CUS__34: 8 SBMU
 SG_ S2A_SUMDATA1_CUS_Reserve1_34 : 0|8@1+ (1,0) [0|255] ""  PC,MBMU
 SG_ S2A_SUMDATA1_CUS_Reserve2_34 : 8|8@1+ (1,0) [0|255] ""  PC,MBMU
 SG_ S2A_SUMDATA1_CUS_Reserve3_34 : 16|8@1+ (1,0) [0|255] ""  PC,MBMU
 SG_ S2A_SUMDATA1_CUS_Reserve4_34 : 24|8@1+ (1,0) [0|255] ""  PC,MBMU
 SG_ S2A_SUMDATA1_CUS_Reserve5_34 : 32|8@1+ (1,0) [0|255] ""  PC,MBMU
 SG_ S2A_SUMDATA1_CUS_Reserve6_34 : 40|8@1+ (1,0) [0|255] ""  PC,MBMU
 SG_ S2A_SUMDATA1_CUS_Reserve7_34 : 48|8@1+ (1,0) [0|255] ""  PC,MBMU
 SG_ S2A_SUMDATA1_CUS_Reserve8_34 : 56|8@1+ (1,0) [0|255] ""  PC,MBMU

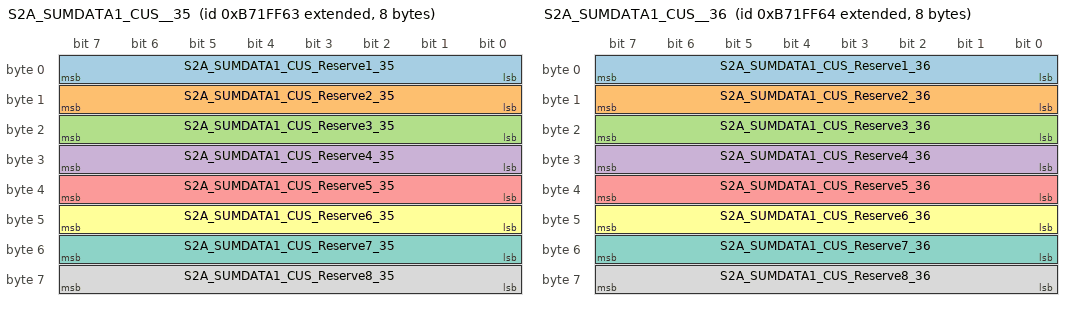
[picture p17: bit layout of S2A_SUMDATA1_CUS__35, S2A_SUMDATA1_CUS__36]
BO_ 2339503971 S2A_SUMDATA1_CUS__35: 8 SBMU
 SG_ S2A_SUMDATA1_CUS_Reserve1_35 : 0|8@1+ (1,0) [0|255] ""  PC,MBMU
 SG_ S2A_SUMDATA1_CUS_Reserve2_35 : 8|8@1+ (1,0) [0|255] ""  PC,MBMU
 SG_ S2A_SUMDATA1_CUS_Reserve3_35 : 16|8@1+ (1,0) [0|255] ""  PC,MBMU
 SG_ S2A_SUMDATA1_CUS_Reserve4_35 : 24|8@1+ (1,0) [0|255] ""  PC,MBMU
 SG_ S2A_SUMDATA1_CUS_Reserve5_35 : 32|8@1+ (1,0) [0|255] ""  PC,MBMU
 SG_ S2A_SUMDATA1_CUS_Reserve6_35 : 40|8@1+ (1,0) [0|255] ""  PC,MBMU
 SG_ S2A_SUMDATA1_CUS_Reserve7_35 : 48|8@1+ (1,0) [0|255] ""  PC,MBMU
 SG_ S2A_SUMDATA1_CUS_Reserve8_35 : 56|8@1+ (1,0) [0|255] ""  PC,MBMU

BO_ 2339503972 S2A_SUMDATA1_CUS__36: 8 SBMU
 SG_ S2A_SUMDATA1_CUS_Reserve1_36 : 0|8@1+ (1,0) [0|255] ""  PC,MBMU
 SG_ S2A_SUMDATA1_CUS_Reserve2_36 : 8|8@1+ (1,0) [0|255] ""  PC,MBMU
 SG_ S2A_SUMDATA1_CUS_Reserve3_36 : 16|8@1+ (1,0) [0|255] ""  PC,MBMU
 SG_ S2A_SUMDATA1_CUS_Reserve4_36 : 24|8@1+ (1,0) [0|255] ""  PC,MBMU
 SG_ S2A_SUMDATA1_CUS_Reserve5_36 : 32|8@1+ (1,0) [0|255] ""  PC,MBMU
 SG_ S2A_SUMDATA1_CUS_Reserve6_36 : 40|8@1+ (1,0) [0|255] ""  PC,MBMU
 SG_ S2A_SUMDATA1_CUS_Reserve7_36 : 48|8@1+ (1,0) [0|255] ""  PC,MBMU
 SG_ S2A_SUMDATA1_CUS_Reserve8_36 : 56|8@1+ (1,0) [0|255] ""  PC,MBMU

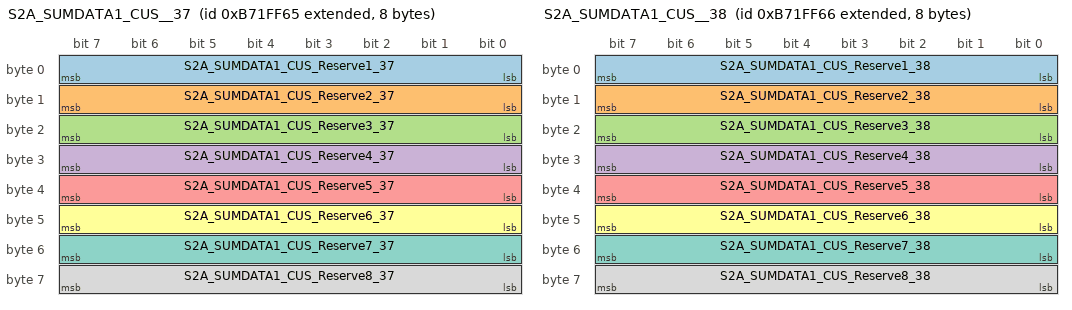
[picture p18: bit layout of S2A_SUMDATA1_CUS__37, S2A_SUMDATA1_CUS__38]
BO_ 2339503973 S2A_SUMDATA1_CUS__37: 8 SBMU
 SG_ S2A_SUMDATA1_CUS_Reserve1_37 : 0|8@1+ (1,0) [0|255] ""  PC,MBMU
 SG_ S2A_SUMDATA1_CUS_Reserve2_37 : 8|8@1+ (1,0) [0|255] ""  PC,MBMU
 SG_ S2A_SUMDATA1_CUS_Reserve3_37 : 16|8@1+ (1,0) [0|255] ""  PC,MBMU
 SG_ S2A_SUMDATA1_CUS_Reserve4_37 : 24|8@1+ (1,0) [0|255] ""  PC,MBMU
 SG_ S2A_SUMDATA1_CUS_Reserve5_37 : 32|8@1+ (1,0) [0|255] ""  PC,MBMU
 SG_ S2A_SUMDATA1_CUS_Reserve6_37 : 40|8@1+ (1,0) [0|255] ""  PC,MBMU
 SG_ S2A_SUMDATA1_CUS_Reserve7_37 : 48|8@1+ (1,0) [0|255] ""  PC,MBMU
 SG_ S2A_SUMDATA1_CUS_Reserve8_37 : 56|8@1+ (1,0) [0|255] ""  PC,MBMU

BO_ 2339503974 S2A_SUMDATA1_CUS__38: 8 SBMU
 SG_ S2A_SUMDATA1_CUS_Reserve1_38 : 0|8@1+ (1,0) [0|255] ""  PC,MBMU
 SG_ S2A_SUMDATA1_CUS_Reserve2_38 : 8|8@1+ (1,0) [0|255] ""  PC,MBMU
 SG_ S2A_SUMDATA1_CUS_Reserve3_38 : 16|8@1+ (1,0) [0|255] ""  PC,MBMU
 SG_ S2A_SUMDATA1_CUS_Reserve4_38 : 24|8@1+ (1,0) [0|255] ""  PC,MBMU
 SG_ S2A_SUMDATA1_CUS_Reserve5_38 : 32|8@1+ (1,0) [0|255] ""  PC,MBMU
 SG_ S2A_SUMDATA1_CUS_Reserve6_38 : 40|8@1+ (1,0) [0|255] ""  PC,MBMU
 SG_ S2A_SUMDATA1_CUS_Reserve7_38 : 48|8@1+ (1,0) [0|255] ""  PC,MBMU
 SG_ S2A_SUMDATA1_CUS_Reserve8_38 : 56|8@1+ (1,0) [0|255] ""  PC,MBMU

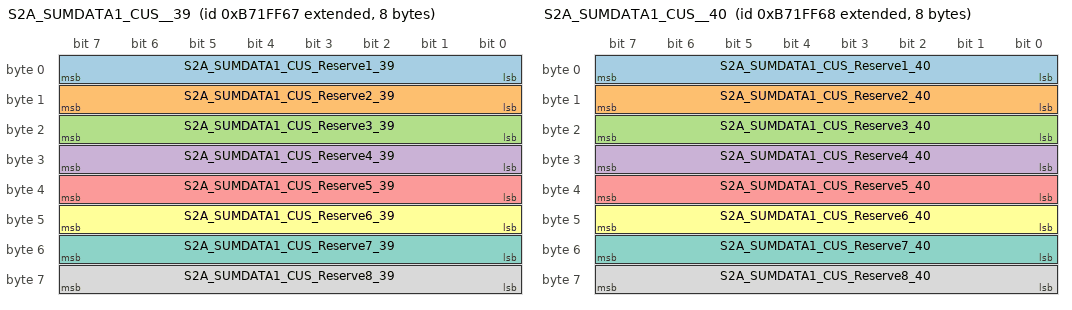
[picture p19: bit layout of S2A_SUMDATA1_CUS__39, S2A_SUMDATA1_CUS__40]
BO_ 2339503975 S2A_SUMDATA1_CUS__39: 8 SBMU
 SG_ S2A_SUMDATA1_CUS_Reserve1_39 : 0|8@1+ (1,0) [0|255] ""  PC,MBMU
 SG_ S2A_SUMDATA1_CUS_Reserve2_39 : 8|8@1+ (1,0) [0|255] ""  PC,MBMU
 SG_ S2A_SUMDATA1_CUS_Reserve3_39 : 16|8@1+ (1,0) [0|255] ""  PC,MBMU
 SG_ S2A_SUMDATA1_CUS_Reserve4_39 : 24|8@1+ (1,0) [0|255] ""  PC,MBMU
 SG_ S2A_SUMDATA1_CUS_Reserve5_39 : 32|8@1+ (1,0) [0|255] ""  PC,MBMU
 SG_ S2A_SUMDATA1_CUS_Reserve6_39 : 40|8@1+ (1,0) [0|255] ""  PC,MBMU
 SG_ S2A_SUMDATA1_CUS_Reserve7_39 : 48|8@1+ (1,0) [0|255] ""  PC,MBMU
 SG_ S2A_SUMDATA1_CUS_Reserve8_39 : 56|8@1+ (1,0) [0|255] ""  PC,MBMU

BO_ 2339503976 S2A_SUMDATA1_CUS__40: 8 SBMU
 SG_ S2A_SUMDATA1_CUS_Reserve1_40 : 0|8@1+ (1,0) [0|255] ""  PC,MBMU
 SG_ S2A_SUMDATA1_CUS_Reserve2_40 : 8|8@1+ (1,0) [0|255] ""  PC,MBMU
 SG_ S2A_SUMDATA1_CUS_Reserve3_40 : 16|8@1+ (1,0) [0|255] ""  PC,MBMU
 SG_ S2A_SUMDATA1_CUS_Reserve4_40 : 24|8@1+ (1,0) [0|255] ""  PC,MBMU
 SG_ S2A_SUMDATA1_CUS_Reserve5_40 : 32|8@1+ (1,0) [0|255] ""  PC,MBMU
 SG_ S2A_SUMDATA1_CUS_Reserve6_40 : 40|8@1+ (1,0) [0|255] ""  PC,MBMU
 SG_ S2A_SUMDATA1_CUS_Reserve7_40 : 48|8@1+ (1,0) [0|255] ""  PC,MBMU
 SG_ S2A_SUMDATA1_CUS_Reserve8_40 : 56|8@1+ (1,0) [0|255] ""  PC,MBMU

BO_ 2339503977 S2A_SUMDATA1_CUS__41: 8 SBMU
 SG_ S2A_SUMDATA1_CUS_Reserve1_41 : 0|8@1+ (1,0) [0|255] ""  PC,MBMU
 SG_ S2A_SUMDATA1_CUS_Reserve2_41 : 8|8@1+ (1,0) [0|255] ""  PC,MBMU
 SG_ S2A_SUMDATA1_CUS_Reserve3_41 : 16|8@1+ (1,0) [0|255] ""  PC,MBMU
 SG_ S2A_SUMDATA1_CUS_Reserve4_41 : 24|8@1+ (1,0) [0|255] ""  PC,MBMU
 SG_ S2A_SUMDATA1_CUS_Reserve5_41 : 32|8@1+ (1,0) [0|255] ""  PC,MBMU
 SG_ S2A_SUMDATA1_CUS_Reserve6_41 : 40|8@1+ (1,0) [0|255] ""  PC,MBMU
 SG_ S2A_SUMDATA1_CUS_Reserve7_41 : 48|8@1+ (1,0) [0|255] ""  PC,MBMU
 SG_ S2A_SUMDATA1_CUS_Reserve8_41 : 56|8@1+ (1,0) [0|255] ""  PC,MBMU

BO_ 2339503978 S2A_SUMDATA1_CUS__42: 8 SBMU
 SG_ S2A_SUMDATA1_CUS_Reserve1_42 : 0|8@1+ (1,0) [0|255] ""  PC,MBMU
 SG_ S2A_SUMDATA1_CUS_Reserve2_42 : 8|8@1+ (1,0) [0|255] ""  PC,MBMU
 SG_ S2A_SUMDATA1_CUS_Reserve3_42 : 16|8@1+ (1,0) [0|255] ""  PC,MBMU
 SG_ S2A_SUMDATA1_CUS_Reserve4_42 : 24|8@1+ (1,0) [0|255] ""  PC,MBMU
 SG_ S2A_SUMDATA1_CUS_Reserve5_42 : 32|8@1+ (1,0) [0|255] ""  PC,MBMU
 SG_ S2A_SUMDATA1_CUS_Reserve6_42 : 40|8@1+ (1,0) [0|255] ""  PC,MBMU
 SG_ S2A_SUMDATA1_CUS_Reserve7_42 : 48|8@1+ (1,0) [0|255] ""  PC,MBMU
 SG_ S2A_SUMDATA1_CUS_Reserve8_42 : 56|8@1+ (1,0) [0|255] ""  PC,MBMU

BO_ 2339503979 S2A_SUMDATA1_CUS__43: 8 SBMU
 SG_ S2A_SUMDATA1_CUS_Reserve1_43 : 0|8@1+ (1,0) [0|255] ""  PC,MBMU
 SG_ S2A_SUMDATA1_CUS_Reserve2_43 : 8|8@1+ (1,0) [0|255] ""  PC,MBMU
 SG_ S2A_SUMDATA1_CUS_Reserve3_43 : 16|8@1+ (1,0) [0|255] ""  PC,MBMU
 SG_ S2A_SUMDATA1_CUS_Reserve4_43 : 24|8@1+ (1,0) [0|255] ""  PC,MBMU
 SG_ S2A_SUMDATA1_CUS_Reserve5_43 : 32|8@1+ (1,0) [0|255] ""  PC,MBMU
 SG_ S2A_SUMDATA1_CUS_Reserve6_43 : 40|8@1+ (1,0) [0|255] ""  PC,MBMU
 SG_ S2A_SUMDATA1_CUS_Reserve7_43 : 48|8@1+ (1,0) [0|255] ""  PC,MBMU
 SG_ S2A_SUMDATA1_CUS_Reserve8_43 : 56|8@1+ (1,0) [0|255] ""  PC,MBMU

BO_ 2339503980 S2A_SUMDATA1_CUS__44: 8 SBMU
 SG_ S2A_SUMDATA1_CUS_Reserve1_44 : 0|8@1+ (1,0) [0|255] ""  PC,MBMU
 SG_ S2A_SUMDATA1_CUS_Reserve2_44 : 8|8@1+ (1,0) [0|255] ""  PC,MBMU
 SG_ S2A_SUMDATA1_CUS_Reserve3_44 : 16|8@1+ (1,0) [0|255] ""  PC,MBMU
 SG_ S2A_SUMDATA1_CUS_Reserve4_44 : 24|8@1+ (1,0) [0|255] ""  PC,MBMU
 SG_ S2A_SUMDATA1_CUS_Reserve5_44 : 32|8@1+ (1,0) [0|255] ""  PC,MBMU
 SG_ S2A_SUMDATA1_CUS_Reserve6_44 : 40|8@1+ (1,0) [0|255] ""  PC,MBMU
 SG_ S2A_SUMDATA1_CUS_Reserve7_44 : 48|8@1+ (1,0) [0|255] ""  PC,MBMU
 SG_ S2A_SUMDATA1_CUS_Reserve8_44 : 56|8@1+ (1,0) [0|255] ""  PC,MBMU

BO_ 2339503981 S2A_SUMDATA1_CUS__45: 8 SBMU
 SG_ S2A_SUMDATA1_CUS_Reserve1_45 : 0|8@1+ (1,0) [0|255] ""  PC,MBMU
 SG_ S2A_SUMDATA1_CUS_Reserve2_45 : 8|8@1+ (1,0) [0|255] ""  PC,MBMU
 SG_ S2A_SUMDATA1_CUS_Reserve3_45 : 16|8@1+ (1,0) [0|255] ""  PC,MBMU
 SG_ S2A_SUMDATA1_CUS_Reserve4_45 : 24|8@1+ (1,0) [0|255] ""  PC,MBMU
 SG_ S2A_SUMDATA1_CUS_Reserve5_45 : 32|8@1+ (1,0) [0|255] ""  PC,MBMU
 SG_ S2A_SUMDATA1_CUS_Reserve6_45 : 40|8@1+ (1,0) [0|255] ""  PC,MBMU
 SG_ S2A_SUMDATA1_CUS_Reserve7_45 : 48|8@1+ (1,0) [0|255] ""  PC,MBMU
 SG_ S2A_SUMDATA1_CUS_Reserve8_45 : 56|8@1+ (1,0) [0|255] ""  PC,MBMU

BO_ 2339503982 S2A_SUMDATA1_CUS__46: 8 SBMU
 SG_ S2A_SUMDATA1_CUS_Reserve1_46 : 0|8@1+ (1,0) [0|255] ""  PC,MBMU
 SG_ S2A_SUMDATA1_CUS_Reserve2_46 : 8|8@1+ (1,0) [0|255] ""  PC,MBMU
 SG_ S2A_SUMDATA1_CUS_Reserve3_46 : 16|8@1+ (1,0) [0|255] ""  PC,MBMU
 SG_ S2A_SUMDATA1_CUS_Reserve4_46 : 24|8@1+ (1,0) [0|255] ""  PC,MBMU
 SG_ S2A_SUMDATA1_CUS_Reserve5_46 : 32|8@1+ (1,0) [0|255] ""  PC,MBMU
 SG_ S2A_SUMDATA1_CUS_Reserve6_46 : 40|8@1+ (1,0) [0|255] ""  PC,MBMU
 SG_ S2A_SUMDATA1_CUS_Reserve7_46 : 48|8@1+ (1,0) [0|255] ""  PC,MBMU
 SG_ S2A_SUMDATA1_CUS_Reserve8_46 : 56|8@1+ (1,0) [0|255] ""  PC,MBMU

BO_ 2339503983 S2A_SUMDATA1_CUS__47: 8 SBMU
 SG_ S2A_SUMDATA1_CUS_Reserve1_47 : 0|8@1+ (1,0) [0|255] ""  PC,MBMU
 SG_ S2A_SUMDATA1_CUS_Reserve2_47 : 8|8@1+ (1,0) [0|255] ""  PC,MBMU
 SG_ S2A_SUMDATA1_CUS_Reserve3_47 : 16|8@1+ (1,0) [0|255] ""  PC,MBMU
 SG_ S2A_SUMDATA1_CUS_Reserve4_47 : 24|8@1+ (1,0) [0|255] ""  PC,MBMU
 SG_ S2A_SUMDATA1_CUS_Reserve5_47 : 32|8@1+ (1,0) [0|255] ""  PC,MBMU
 SG_ S2A_SUMDATA1_CUS_Reserve6_47 : 40|8@1+ (1,0) [0|255] ""  PC,MBMU
 SG_ S2A_SUMDATA1_CUS_Reserve7_47 : 48|8@1+ (1,0) [0|255] ""  PC,MBMU
 SG_ S2A_SUMDATA1_CUS_Reserve8_47 : 56|8@1+ (1,0) [0|255] ""  PC,MBMU

BO_ 2339503984 S2A_SUMDATA1_CUS__48: 8 SBMU
 SG_ S2A_SUMDATA1_CUS_Reserve1_48 : 0|8@1+ (1,0) [0|255] ""  PC,MBMU
 SG_ S2A_SUMDATA1_CUS_Reserve2_48 : 8|8@1+ (1,0) [0|255] ""  PC,MBMU
 SG_ S2A_SUMDATA1_CUS_Reserve3_48 : 16|8@1+ (1,0) [0|255] ""  PC,MBMU
 SG_ S2A_SUMDATA1_CUS_Reserve4_48 : 24|8@1+ (1,0) [0|255] ""  PC,MBMU
 SG_ S2A_SUMDATA1_CUS_Reserve5_48 : 32|8@1+ (1,0) [0|255] ""  PC,MBMU
 SG_ S2A_SUMDATA1_CUS_Reserve6_48 : 40|8@1+ (1,0) [0|255] ""  PC,MBMU
 SG_ S2A_SUMDATA1_CUS_Reserve7_48 : 48|8@1+ (1,0) [0|255] ""  PC,MBMU
 SG_ S2A_SUMDATA1_CUS_Reserve8_48 : 56|8@1+ (1,0) [0|255] ""  PC,MBMU

BO_ 2339503985 S2A_SUMDATA1_CUS__49: 8 SBMU
 SG_ S2A_SUMDATA1_CUS_Reserve1_49 : 0|8@1+ (1,0) [0|255] ""  PC,MBMU
 SG_ S2A_SUMDATA1_CUS_Reserve2_49 : 8|8@1+ (1,0) [0|255] ""  PC,MBMU
 SG_ S2A_SUMDATA1_CUS_Reserve3_49 : 16|8@1+ (1,0) [0|255] ""  PC,MBMU
 SG_ S2A_SUMDATA1_CUS_Reserve4_49 : 24|8@1+ (1,0) [0|255] ""  PC,MBMU
 SG_ S2A_SUMDATA1_CUS_Reserve5_49 : 32|8@1+ (1,0) [0|255] ""  PC,MBMU
 SG_ S2A_SUMDATA1_CUS_Reserve6_49 : 40|8@1+ (1,0) [0|255] ""  PC,MBMU
 SG_ S2A_SUMDATA1_CUS_Reserve7_49 : 48|8@1+ (1,0) [0|255] ""  PC,MBMU
 SG_ S2A_SUMDATA1_CUS_Reserve8_49 : 56|8@1+ (1,0) [0|255] ""  PC,MBMU

BO_ 2339503986 S2A_SUMDATA1_CUS__50: 8 SBMU
 SG_ S2A_SUMDATA1_CUS_Reserve1_50 : 0|8@1+ (1,0) [0|255] ""  PC,MBMU
 SG_ S2A_SUMDATA1_CUS_Reserve2_50 : 8|8@1+ (1,0) [0|255] ""  PC,MBMU
 SG_ S2A_SUMDATA1_CUS_Reserve3_50 : 16|8@1+ (1,0) [0|255] ""  PC,MBMU
 SG_ S2A_SUMDATA1_CUS_Reserve4_50 : 24|8@1+ (1,0) [0|255] ""  PC,MBMU
 SG_ S2A_SUMDATA1_CUS_Reserve5_50 : 32|8@1+ (1,0) [0|255] ""  PC,MBMU
 SG_ S2A_SUMDATA1_CUS_Reserve6_50 : 40|8@1+ (1,0) [0|255] ""  PC,MBMU
 SG_ S2A_SUMDATA1_CUS_Reserve7_50 : 48|8@1+ (1,0) [0|255] ""  PC,MBMU
 SG_ S2A_SUMDATA1_CUS_Reserve8_50 : 56|8@1+ (1,0) [0|255] ""  PC,MBMU

BO_ 2339503987 S2A_SUMDATA1_CUS__51: 8 SBMU
 SG_ S2A_SUMDATA1_CUS_Reserve1_51 : 0|8@1+ (1,0) [0|255] ""  PC,MBMU
 SG_ S2A_SUMDATA1_CUS_Reserve2_51 : 8|8@1+ (1,0) [0|255] ""  PC,MBMU
 SG_ S2A_SUMDATA1_CUS_Reserve3_51 : 16|8@1+ (1,0) [0|255] ""  PC,MBMU
 SG_ S2A_SUMDATA1_CUS_Reserve4_51 : 24|8@1+ (1,0) [0|255] ""  PC,MBMU
 SG_ S2A_SUMDATA1_CUS_Reserve5_51 : 32|8@1+ (1,0) [0|255] ""  PC,MBMU
 SG_ S2A_SUMDATA1_CUS_Reserve6_51 : 40|8@1+ (1,0) [0|255] ""  PC,MBMU
 SG_ S2A_SUMDATA1_CUS_Reserve7_51 : 48|8@1+ (1,0) [0|255] ""  PC,MBMU
 SG_ S2A_SUMDATA1_CUS_Reserve8_51 : 56|8@1+ (1,0) [0|255] ""  PC,MBMU

BO_ 2339503988 S2A_SUMDATA1_CUS__52: 8 SBMU
 SG_ S2A_SUMDATA1_CUS_Reserve1_52 : 0|8@1+ (1,0) [0|255] ""  PC,MBMU
 SG_ S2A_SUMDATA1_CUS_Reserve2_52 : 8|8@1+ (1,0) [0|255] ""  PC,MBMU
 SG_ S2A_SUMDATA1_CUS_Reserve3_52 : 16|8@1+ (1,0) [0|255] ""  PC,MBMU
 SG_ S2A_SUMDATA1_CUS_Reserve4_52 : 24|8@1+ (1,0) [0|255] ""  PC,MBMU
 SG_ S2A_SUMDATA1_CUS_Reserve5_52 : 32|8@1+ (1,0) [0|255] ""  PC,MBMU
 SG_ S2A_SUMDATA1_CUS_Reserve6_52 : 40|8@1+ (1,0) [0|255] ""  PC,MBMU
 SG_ S2A_SUMDATA1_CUS_Reserve7_52 : 48|8@1+ (1,0) [0|255] ""  PC,MBMU
 SG_ S2A_SUMDATA1_CUS_Reserve8_52 : 56|8@1+ (1,0) [0|255] ""  PC,MBMU

BO_ 2339503989 S2A_SUMDATA1_CUS__53: 8 SBMU
 SG_ S2A_SUMDATA1_CUS_Reserve1_53 : 0|8@1+ (1,0) [0|255] ""  PC,MBMU
 SG_ S2A_SUMDATA1_CUS_Reserve2_53 : 8|8@1+ (1,0) [0|255] ""  PC,MBMU
 SG_ S2A_SUMDATA1_CUS_Reserve3_53 : 16|8@1+ (1,0) [0|255] ""  PC,MBMU
 SG_ S2A_SUMDATA1_CUS_Reserve4_53 : 24|8@1+ (1,0) [0|255] ""  PC,MBMU
 SG_ S2A_SUMDATA1_CUS_Reserve5_53 : 32|8@1+ (1,0) [0|255] ""  PC,MBMU
 SG_ S2A_SUMDATA1_CUS_Reserve6_53 : 40|8@1+ (1,0) [0|255] ""  PC,MBMU
 SG_ S2A_SUMDATA1_CUS_Reserve7_53 : 48|8@1+ (1,0) [0|255] ""  PC,MBMU
 SG_ S2A_SUMDATA1_CUS_Reserve8_53 : 56|8@1+ (1,0) [0|255] ""  PC,MBMU

BO_ 2339503990 S2A_SUMDATA1_CUS__54: 8 SBMU
 SG_ S2A_SUMDATA1_CUS_Reserve1_54 : 0|8@1+ (1,0) [0|255] ""  PC,MBMU
 SG_ S2A_SUMDATA1_CUS_Reserve2_54 : 8|8@1+ (1,0) [0|255] ""  PC,MBMU
 SG_ S2A_SUMDATA1_CUS_Reserve3_54 : 16|8@1+ (1,0) [0|255] ""  PC,MBMU
 SG_ S2A_SUMDATA1_CUS_Reserve4_54 : 24|8@1+ (1,0) [0|255] ""  PC,MBMU
 SG_ S2A_SUMDATA1_CUS_Reserve5_54 : 32|8@1+ (1,0) [0|255] ""  PC,MBMU
 SG_ S2A_SUMDATA1_CUS_Reserve6_54 : 40|8@1+ (1,0) [0|255] ""  PC,MBMU
 SG_ S2A_SUMDATA1_CUS_Reserve7_54 : 48|8@1+ (1,0) [0|255] ""  PC,MBMU
 SG_ S2A_SUMDATA1_CUS_Reserve8_54 : 56|8@1+ (1,0) [0|255] ""  PC,MBMU

BO_ 2339503991 S2A_SUMDATA1_CUS__55: 8 SBMU
 SG_ S2A_SUMDATA1_CUS_Reserve1_55 : 0|8@1+ (1,0) [0|255] ""  PC,MBMU
 SG_ S2A_SUMDATA1_CUS_Reserve2_55 : 8|8@1+ (1,0) [0|255] ""  PC,MBMU
 SG_ S2A_SUMDATA1_CUS_Reserve3_55 : 16|8@1+ (1,0) [0|255] ""  PC,MBMU
 SG_ S2A_SUMDATA1_CUS_Reserve4_55 : 24|8@1+ (1,0) [0|255] ""  PC,MBMU
 SG_ S2A_SUMDATA1_CUS_Reserve5_55 : 32|8@1+ (1,0) [0|255] ""  PC,MBMU
 SG_ S2A_SUMDATA1_CUS_Reserve6_55 : 40|8@1+ (1,0) [0|255] ""  PC,MBMU
 SG_ S2A_SUMDATA1_CUS_Reserve7_55 : 48|8@1+ (1,0) [0|255] ""  PC,MBMU
 SG_ S2A_SUMDATA1_CUS_Reserve8_55 : 56|8@1+ (1,0) [0|255] ""  PC,MBMU

BO_ 2339503992 S2A_SUMDATA1_CUS__56: 8 SBMU
 SG_ S2A_SUMDATA1_CUS_Reserve1_56 : 0|8@1+ (1,0) [0|255] ""  PC,MBMU
 SG_ S2A_SUMDATA1_CUS_Reserve2_56 : 8|8@1+ (1,0) [0|255] ""  PC,MBMU
 SG_ S2A_SUMDATA1_CUS_Reserve3_56 : 16|8@1+ (1,0) [0|255] ""  PC,MBMU
 SG_ S2A_SUMDATA1_CUS_Reserve4_56 : 24|8@1+ (1,0) [0|255] ""  PC,MBMU
 SG_ S2A_SUMDATA1_CUS_Reserve5_56 : 32|8@1+ (1,0) [0|255] ""  PC,MBMU
 SG_ S2A_SUMDATA1_CUS_Reserve6_56 : 40|8@1+ (1,0) [0|255] ""  PC,MBMU
 SG_ S2A_SUMDATA1_CUS_Reserve7_56 : 48|8@1+ (1,0) [0|255] ""  PC,MBMU
 SG_ S2A_SUMDATA1_CUS_Reserve8_56 : 56|8@1+ (1,0) [0|255] ""  PC,MBMU

BO_ 2339503993 S2A_SUMDATA1_CUS__57: 8 SBMU
 SG_ S2A_SUMDATA1_CUS_Reserve1_57 : 0|8@1+ (1,0) [0|255] ""  PC,MBMU
 SG_ S2A_SUMDATA1_CUS_Reserve2_57 : 8|8@1+ (1,0) [0|255] ""  PC,MBMU
 SG_ S2A_SUMDATA1_CUS_Reserve3_57 : 16|8@1+ (1,0) [0|255] ""  PC,MBMU
 SG_ S2A_SUMDATA1_CUS_Reserve4_57 : 24|8@1+ (1,0) [0|255] ""  PC,MBMU
 SG_ S2A_SUMDATA1_CUS_Reserve5_57 : 32|8@1+ (1,0) [0|255] ""  PC,MBMU
 SG_ S2A_SUMDATA1_CUS_Reserve6_57 : 40|8@1+ (1,0) [0|255] ""  PC,MBMU
 SG_ S2A_SUMDATA1_CUS_Reserve7_57 : 48|8@1+ (1,0) [0|255] ""  PC,MBMU
 SG_ S2A_SUMDATA1_CUS_Reserve8_57 : 56|8@1+ (1,0) [0|255] ""  PC,MBMU

BO_ 2339503994 S2A_SUMDATA1_CUS__58: 8 SBMU
 SG_ S2A_SUMDATA1_CUS_Reserve1_58 : 0|8@1+ (1,0) [0|255] ""  PC,MBMU
 SG_ S2A_SUMDATA1_CUS_Reserve2_58 : 8|8@1+ (1,0) [0|255] ""  PC,MBMU
 SG_ S2A_SUMDATA1_CUS_Reserve3_58 : 16|8@1+ (1,0) [0|255] ""  PC,MBMU
 SG_ S2A_SUMDATA1_CUS_Reserve4_58 : 24|8@1+ (1,0) [0|255] ""  PC,MBMU
 SG_ S2A_SUMDATA1_CUS_Reserve5_58 : 32|8@1+ (1,0) [0|255] ""  PC,MBMU
 SG_ S2A_SUMDATA1_CUS_Reserve6_58 : 40|8@1+ (1,0) [0|255] ""  PC,MBMU
 SG_ S2A_SUMDATA1_CUS_Reserve7_58 : 48|8@1+ (1,0) [0|255] ""  PC,MBMU
 SG_ S2A_SUMDATA1_CUS_Reserve8_58 : 56|8@1+ (1,0) [0|255] ""  PC,MBMU

BO_ 2339503995 S2A_SUMDATA1_CUS__59: 8 SBMU
 SG_ S2A_SUMDATA1_CUS_Reserve1_59 : 0|8@1+ (1,0) [0|255] ""  PC,MBMU
 SG_ S2A_SUMDATA1_CUS_Reserve2_59 : 8|8@1+ (1,0) [0|255] ""  PC,MBMU
 SG_ S2A_SUMDATA1_CUS_Reserve3_59 : 16|8@1+ (1,0) [0|255] ""  PC,MBMU
 SG_ S2A_SUMDATA1_CUS_Reserve4_59 : 24|8@1+ (1,0) [0|255] ""  PC,MBMU
 SG_ S2A_SUMDATA1_CUS_Reserve5_59 : 32|8@1+ (1,0) [0|255] ""  PC,MBMU
 SG_ S2A_SUMDATA1_CUS_Reserve6_59 : 40|8@1+ (1,0) [0|255] ""  PC,MBMU
 SG_ S2A_SUMDATA1_CUS_Reserve7_59 : 48|8@1+ (1,0) [0|255] ""  PC,MBMU
 SG_ S2A_SUMDATA1_CUS_Reserve8_59 : 56|8@1+ (1,0) [0|255] ""  PC,MBMU

BO_ 2339503996 S2A_SUMDATA1_CUS__60: 8 SBMU
 SG_ S2A_SUMDATA1_CUS_Reserve1_60 : 0|8@1+ (1,0) [0|255] ""  PC,MBMU
 SG_ S2A_SUMDATA1_CUS_Reserve2_60 : 8|8@1+ (1,0) [0|255] ""  PC,MBMU
 SG_ S2A_SUMDATA1_CUS_Reserve3_60 : 16|8@1+ (1,0) [0|255] ""  PC,MBMU
 SG_ S2A_SUMDATA1_CUS_Reserve4_60 : 24|8@1+ (1,0) [0|255] ""  PC,MBMU
 SG_ S2A_SUMDATA1_CUS_Reserve5_60 : 32|8@1+ (1,0) [0|255] ""  PC,MBMU
 SG_ S2A_SUMDATA1_CUS_Reserve6_60 : 40|8@1+ (1,0) [0|255] ""  PC,MBMU
 SG_ S2A_SUMDATA1_CUS_Reserve7_60 : 48|8@1+ (1,0) [0|255] ""  PC,MBMU
 SG_ S2A_SUMDATA1_CUS_Reserve8_60 : 56|8@1+ (1,0) [0|255] ""  PC,MBMU

BO_ 2339503997 S2A_SUMDATA1_CUS__61: 8 SBMU
 SG_ S2A_SUMDATA1_CUS_Reserve1_61 : 0|8@1+ (1,0) [0|255] ""  PC,MBMU
 SG_ S2A_SUMDATA1_CUS_Reserve2_61 : 8|8@1+ (1,0) [0|255] ""  PC,MBMU
 SG_ S2A_SUMDATA1_CUS_Reserve3_61 : 16|8@1+ (1,0) [0|255] ""  PC,MBMU
 SG_ S2A_SUMDATA1_CUS_Reserve4_61 : 24|8@1+ (1,0) [0|255] ""  PC,MBMU
 SG_ S2A_SUMDATA1_CUS_Reserve5_61 : 32|8@1+ (1,0) [0|255] ""  PC,MBMU
 SG_ S2A_SUMDATA1_CUS_Reserve6_61 : 40|8@1+ (1,0) [0|255] ""  PC,MBMU
 SG_ S2A_SUMDATA1_CUS_Reserve7_61 : 48|8@1+ (1,0) [0|255] ""  PC,MBMU
 SG_ S2A_SUMDATA1_CUS_Reserve8_61 : 56|8@1+ (1,0) [0|255] ""  PC,MBMU

BO_ 2339503998 S2A_SUMDATA1_CUS__62: 8 SBMU
 SG_ S2A_SUMDATA1_CUS_Reserve1_62 : 0|8@1+ (1,0) [0|255] ""  PC,MBMU
 SG_ S2A_SUMDATA1_CUS_Reserve2_62 : 8|8@1+ (1,0) [0|255] ""  PC,MBMU
 SG_ S2A_SUMDATA1_CUS_Reserve3_62 : 16|8@1+ (1,0) [0|255] ""  PC,MBMU
 SG_ S2A_SUMDATA1_CUS_Reserve4_62 : 24|8@1+ (1,0) [0|255] ""  PC,MBMU
 SG_ S2A_SUMDATA1_CUS_Reserve5_62 : 32|8@1+ (1,0) [0|255] ""  PC,MBMU
 SG_ S2A_SUMDATA1_CUS_Reserve6_62 : 40|8@1+ (1,0) [0|255] ""  PC,MBMU
 SG_ S2A_SUMDATA1_CUS_Reserve7_62 : 48|8@1+ (1,0) [0|255] ""  PC,MBMU
 SG_ S2A_SUMDATA1_CUS_Reserve8_62 : 56|8@1+ (1,0) [0|255] ""  PC,MBMU

BO_ 2339503999 S2A_SUMDATA1_CUS__63: 8 SBMU
 SG_ S2A_SUMDATA1_CUS_Reserve1_63 : 0|8@1+ (1,0) [0|255] ""  PC,MBMU
 SG_ S2A_SUMDATA1_CUS_Reserve2_63 : 8|8@1+ (1,0) [0|255] ""  PC,MBMU
 SG_ S2A_SUMDATA1_CUS_Reserve3_63 : 16|8@1+ (1,0) [0|255] ""  PC,MBMU
 SG_ S2A_SUMDATA1_CUS_Reserve4_63 : 24|8@1+ (1,0) [0|255] ""  PC,MBMU
 SG_ S2A_SUMDATA1_CUS_Reserve5_63 : 32|8@1+ (1,0) [0|255] ""  PC,MBMU
 SG_ S2A_SUMDATA1_CUS_Reserve6_63 : 40|8@1+ (1,0) [0|255] ""  PC,MBMU
 SG_ S2A_SUMDATA1_CUS_Reserve7_63 : 48|8@1+ (1,0) [0|255] ""  PC,MBMU
 SG_ S2A_SUMDATA1_CUS_Reserve8_63 : 56|8@1+ (1,0) [0|255] ""  PC,MBMU

BO_ 2339569473 S2A_SUMDATA2_CUS__01: 8 SBMU
 SG_ S2A_SUMDATA2_CUS_Reserve1_01 : 0|8@1+ (1,0) [0|255] ""  PC,MBMU
 SG_ S2A_SUMDATA2_CUS_Reserve2_01 : 8|8@1+ (1,0) [0|255] ""  PC,MBMU
 SG_ S2A_SUMDATA2_CUS_Reserve3_01 : 16|8@1+ (1,0) [0|255] ""  PC,MBMU
 SG_ S2A_SUMDATA2_CUS_Reserve4_01 : 24|8@1+ (1,0) [0|255] ""  PC,MBMU
 SG_ S2A_SUMDATA2_CUS_Reserve5_01 : 32|8@1+ (1,0) [0|255] ""  PC,MBMU
 SG_ S2A_SUMDATA2_CUS_Reserve6_01 : 40|8@1+ (1,0) [0|255] ""  PC,MBMU
 SG_ S2A_SUMDATA2_CUS_Reserve7_01 : 48|8@1+ (1,0) [0|255] ""  PC,MBMU
 SG_ S2A_SUMDATA2_CUS_Reserve8_01 : 56|8@1+ (1,0) [0|255] ""  PC,MBMU

BO_ 2339569474 S2A_SUMDATA2_CUS__02: 8 SBMU
 SG_ S2A_SUMDATA2_CUS_Reserve1_02 : 0|8@1+ (1,0) [0|255] ""  PC,MBMU
 SG_ S2A_SUMDATA2_CUS_Reserve2_02 : 8|8@1+ (1,0) [0|255] ""  PC,MBMU
 SG_ S2A_SUMDATA2_CUS_Reserve3_02 : 16|8@1+ (1,0) [0|255] ""  PC,MBMU
 SG_ S2A_SUMDATA2_CUS_Reserve4_02 : 24|8@1+ (1,0) [0|255] ""  PC,MBMU
 SG_ S2A_SUMDATA2_CUS_Reserve5_02 : 32|8@1+ (1,0) [0|255] ""  PC,MBMU
 SG_ S2A_SUMDATA2_CUS_Reserve6_02 : 40|8@1+ (1,0) [0|255] ""  PC,MBMU
 SG_ S2A_SUMDATA2_CUS_Reserve7_02 : 48|8@1+ (1,0) [0|255] ""  PC,MBMU
 SG_ S2A_SUMDATA2_CUS_Reserve8_02 : 56|8@1+ (1,0) [0|255] ""  PC,MBMU

BO_ 2339569475 S2A_SUMDATA2_CUS__03: 8 SBMU
 SG_ S2A_SUMDATA2_CUS_Reserve1_03 : 0|8@1+ (1,0) [0|255] ""  PC,MBMU
 SG_ S2A_SUMDATA2_CUS_Reserve2_03 : 8|8@1+ (1,0) [0|255] ""  PC,MBMU
 SG_ S2A_SUMDATA2_CUS_Reserve3_03 : 16|8@1+ (1,0) [0|255] ""  PC,MBMU
 SG_ S2A_SUMDATA2_CUS_Reserve4_03 : 24|8@1+ (1,0) [0|255] ""  PC,MBMU
 SG_ S2A_SUMDATA2_CUS_Reserve5_03 : 32|8@1+ (1,0) [0|255] ""  PC,MBMU
 SG_ S2A_SUMDATA2_CUS_Reserve6_03 : 40|8@1+ (1,0) [0|255] ""  PC,MBMU
 SG_ S2A_SUMDATA2_CUS_Reserve7_03 : 48|8@1+ (1,0) [0|255] ""  PC,MBMU
 SG_ S2A_SUMDATA2_CUS_Reserve8_03 : 56|8@1+ (1,0) [0|255] ""  PC,MBMU

BO_ 2339569476 S2A_SUMDATA2_CUS__04: 8 SBMU
 SG_ S2A_SUMDATA2_CUS_Reserve1_04 : 0|8@1+ (1,0) [0|255] ""  PC,MBMU
 SG_ S2A_SUMDATA2_CUS_Reserve2_04 : 8|8@1+ (1,0) [0|255] ""  PC,MBMU
 SG_ S2A_SUMDATA2_CUS_Reserve3_04 : 16|8@1+ (1,0) [0|255] ""  PC,MBMU
 SG_ S2A_SUMDATA2_CUS_Reserve4_04 : 24|8@1+ (1,0) [0|255] ""  PC,MBMU
 SG_ S2A_SUMDATA2_CUS_Reserve5_04 : 32|8@1+ (1,0) [0|255] ""  PC,MBMU
 SG_ S2A_SUMDATA2_CUS_Reserve6_04 : 40|8@1+ (1,0) [0|255] ""  PC,MBMU
 SG_ S2A_SUMDATA2_CUS_Reserve7_04 : 48|8@1+ (1,0) [0|255] ""  PC,MBMU
 SG_ S2A_SUMDATA2_CUS_Reserve8_04 : 56|8@1+ (1,0) [0|255] ""  PC,MBMU

BO_ 2339569477 S2A_SUMDATA2_CUS__05: 8 SBMU
 SG_ S2A_SUMDATA2_CUS_Reserve1_05 : 0|8@1+ (1,0) [0|255] ""  PC,MBMU
 SG_ S2A_SUMDATA2_CUS_Reserve2_05 : 8|8@1+ (1,0) [0|255] ""  PC,MBMU
 SG_ S2A_SUMDATA2_CUS_Reserve3_05 : 16|8@1+ (1,0) [0|255] ""  PC,MBMU
 SG_ S2A_SUMDATA2_CUS_Reserve4_05 : 24|8@1+ (1,0) [0|255] ""  PC,MBMU
 SG_ S2A_SUMDATA2_CUS_Reserve5_05 : 32|8@1+ (1,0) [0|255] ""  PC,MBMU
 SG_ S2A_SUMDATA2_CUS_Reserve6_05 : 40|8@1+ (1,0) [0|255] ""  PC,MBMU
 SG_ S2A_SUMDATA2_CUS_Reserve7_05 : 48|8@1+ (1,0) [0|255] ""  PC,MBMU
 SG_ S2A_SUMDATA2_CUS_Reserve8_05 : 56|8@1+ (1,0) [0|255] ""  PC,MBMU

BO_ 2339569478 S2A_SUMDATA2_CUS__06: 8 SBMU
 SG_ S2A_SUMDATA2_CUS_Reserve1_06 : 0|8@1+ (1,0) [0|255] ""  PC,MBMU
 SG_ S2A_SUMDATA2_CUS_Reserve2_06 : 8|8@1+ (1,0) [0|255] ""  PC,MBMU
 SG_ S2A_SUMDATA2_CUS_Reserve3_06 : 16|8@1+ (1,0) [0|255] ""  PC,MBMU
 SG_ S2A_SUMDATA2_CUS_Reserve4_06 : 24|8@1+ (1,0) [0|255] ""  PC,MBMU
 SG_ S2A_SUMDATA2_CUS_Reserve5_06 : 32|8@1+ (1,0) [0|255] ""  PC,MBMU
 SG_ S2A_SUMDATA2_CUS_Reserve6_06 : 40|8@1+ (1,0) [0|255] ""  PC,MBMU
 SG_ S2A_SUMDATA2_CUS_Reserve7_06 : 48|8@1+ (1,0) [0|255] ""  PC,MBMU
 SG_ S2A_SUMDATA2_CUS_Reserve8_06 : 56|8@1+ (1,0) [0|255] ""  PC,MBMU

BO_ 2339569479 S2A_SUMDATA2_CUS__07: 8 SBMU
 SG_ S2A_SUMDATA2_CUS_Reserve1_07 : 0|8@1+ (1,0) [0|255] ""  PC,MBMU
 SG_ S2A_SUMDATA2_CUS_Reserve2_07 : 8|8@1+ (1,0) [0|255] ""  PC,MBMU
 SG_ S2A_SUMDATA2_CUS_Reserve3_07 : 16|8@1+ (1,0) [0|255] ""  PC,MBMU
 SG_ S2A_SUMDATA2_CUS_Reserve4_07 : 24|8@1+ (1,0) [0|255] ""  PC,MBMU
 SG_ S2A_SUMDATA2_CUS_Reserve5_07 : 32|8@1+ (1,0) [0|255] ""  PC,MBMU
 SG_ S2A_SUMDATA2_CUS_Reserve6_07 : 40|8@1+ (1,0) [0|255] ""  PC,MBMU
 SG_ S2A_SUMDATA2_CUS_Reserve7_07 : 48|8@1+ (1,0) [0|255] ""  PC,MBMU
 SG_ S2A_SUMDATA2_CUS_Reserve8_07 : 56|8@1+ (1,0) [0|255] ""  PC,MBMU

BO_ 2339569480 S2A_SUMDATA2_CUS__08: 8 SBMU
 SG_ S2A_SUMDATA2_CUS_Reserve1_08 : 0|8@1+ (1,0) [0|255] ""  PC,MBMU
 SG_ S2A_SUMDATA2_CUS_Reserve2_08 : 8|8@1+ (1,0) [0|255] ""  PC,MBMU
 SG_ S2A_SUMDATA2_CUS_Reserve3_08 : 16|8@1+ (1,0) [0|255] ""  PC,MBMU
 SG_ S2A_SUMDATA2_CUS_Reserve4_08 : 24|8@1+ (1,0) [0|255] ""  PC,MBMU
 SG_ S2A_SUMDATA2_CUS_Reserve5_08 : 32|8@1+ (1,0) [0|255] ""  PC,MBMU
 SG_ S2A_SUMDATA2_CUS_Reserve6_08 : 40|8@1+ (1,0) [0|255] ""  PC,MBMU
 SG_ S2A_SUMDATA2_CUS_Reserve7_08 : 48|8@1+ (1,0) [0|255] ""  PC,MBMU
 SG_ S2A_SUMDATA2_CUS_Reserve8_08 : 56|8@1+ (1,0) [0|255] ""  PC,MBMU

BO_ 2339569481 S2A_SUMDATA2_CUS__09: 8 SBMU
 SG_ S2A_SUMDATA2_CUS_Reserve1_09 : 0|8@1+ (1,0) [0|255] ""  PC,MBMU
 SG_ S2A_SUMDATA2_CUS_Reserve2_09 : 8|8@1+ (1,0) [0|255] ""  PC,MBMU
 SG_ S2A_SUMDATA2_CUS_Reserve3_09 : 16|8@1+ (1,0) [0|255] ""  PC,MBMU
 SG_ S2A_SUMDATA2_CUS_Reserve4_09 : 24|8@1+ (1,0) [0|255] ""  PC,MBMU
 SG_ S2A_SUMDATA2_CUS_Reserve5_09 : 32|8@1+ (1,0) [0|255] ""  PC,MBMU
 SG_ S2A_SUMDATA2_CUS_Reserve6_09 : 40|8@1+ (1,0) [0|255] ""  PC,MBMU
 SG_ S2A_SUMDATA2_CUS_Reserve7_09 : 48|8@1+ (1,0) [0|255] ""  PC,MBMU
 SG_ S2A_SUMDATA2_CUS_Reserve8_09 : 56|8@1+ (1,0) [0|255] ""  PC,MBMU

BO_ 2339569482 S2A_SUMDATA2_CUS__10: 8 SBMU
 SG_ S2A_SUMDATA2_CUS_Reserve1_10 : 0|8@1+ (1,0) [0|255] ""  PC,MBMU
 SG_ S2A_SUMDATA2_CUS_Reserve2_10 : 8|8@1+ (1,0) [0|255] ""  PC,MBMU
 SG_ S2A_SUMDATA2_CUS_Reserve3_10 : 16|8@1+ (1,0) [0|255] ""  PC,MBMU
 SG_ S2A_SUMDATA2_CUS_Reserve4_10 : 24|8@1+ (1,0) [0|255] ""  PC,MBMU
 SG_ S2A_SUMDATA2_CUS_Reserve5_10 : 32|8@1+ (1,0) [0|255] ""  PC,MBMU
 SG_ S2A_SUMDATA2_CUS_Reserve6_10 : 40|8@1+ (1,0) [0|255] ""  PC,MBMU
 SG_ S2A_SUMDATA2_CUS_Reserve7_10 : 48|8@1+ (1,0) [0|255] ""  PC,MBMU
 SG_ S2A_SUMDATA2_CUS_Reserve8_10 : 56|8@1+ (1,0) [0|255] ""  PC,MBMU

BO_ 2339569483 S2A_SUMDATA2_CUS__11: 8 SBMU
 SG_ S2A_SUMDATA2_CUS_Reserve1_11 : 0|8@1+ (1,0) [0|255] ""  PC,MBMU
 SG_ S2A_SUMDATA2_CUS_Reserve2_11 : 8|8@1+ (1,0) [0|255] ""  PC,MBMU
 SG_ S2A_SUMDATA2_CUS_Reserve3_11 : 16|8@1+ (1,0) [0|255] ""  PC,MBMU
 SG_ S2A_SUMDATA2_CUS_Reserve4_11 : 24|8@1+ (1,0) [0|255] ""  PC,MBMU
 SG_ S2A_SUMDATA2_CUS_Reserve5_11 : 32|8@1+ (1,0) [0|255] ""  PC,MBMU
 SG_ S2A_SUMDATA2_CUS_Reserve6_11 : 40|8@1+ (1,0) [0|255] ""  PC,MBMU
 SG_ S2A_SUMDATA2_CUS_Reserve7_11 : 48|8@1+ (1,0) [0|255] ""  PC,MBMU
 SG_ S2A_SUMDATA2_CUS_Reserve8_11 : 56|8@1+ (1,0) [0|255] ""  PC,MBMU

BO_ 2339569484 S2A_SUMDATA2_CUS__12: 8 SBMU
 SG_ S2A_SUMDATA2_CUS_Reserve1_12 : 0|8@1+ (1,0) [0|255] ""  PC,MBMU
 SG_ S2A_SUMDATA2_CUS_Reserve2_12 : 8|8@1+ (1,0) [0|255] ""  PC,MBMU
 SG_ S2A_SUMDATA2_CUS_Reserve3_12 : 16|8@1+ (1,0) [0|255] ""  PC,MBMU
 SG_ S2A_SUMDATA2_CUS_Reserve4_12 : 24|8@1+ (1,0) [0|255] ""  PC,MBMU
 SG_ S2A_SUMDATA2_CUS_Reserve5_12 : 32|8@1+ (1,0) [0|255] ""  PC,MBMU
 SG_ S2A_SUMDATA2_CUS_Reserve6_12 : 40|8@1+ (1,0) [0|255] ""  PC,MBMU
 SG_ S2A_SUMDATA2_CUS_Reserve7_12 : 48|8@1+ (1,0) [0|255] ""  PC,MBMU
 SG_ S2A_SUMDATA2_CUS_Reserve8_12 : 56|8@1+ (1,0) [0|255] ""  PC,MBMU

BO_ 2339569485 S2A_SUMDATA2_CUS__13: 8 SBMU
 SG_ S2A_SUMDATA2_CUS_Reserve1_13 : 0|8@1+ (1,0) [0|255] ""  PC,MBMU
 SG_ S2A_SUMDATA2_CUS_Reserve2_13 : 8|8@1+ (1,0) [0|255] ""  PC,MBMU
 SG_ S2A_SUMDATA2_CUS_Reserve3_13 : 16|8@1+ (1,0) [0|255] ""  PC,MBMU
 SG_ S2A_SUMDATA2_CUS_Reserve4_13 : 24|8@1+ (1,0) [0|255] ""  PC,MBMU
 SG_ S2A_SUMDATA2_CUS_Reserve5_13 : 32|8@1+ (1,0) [0|255] ""  PC,MBMU
 SG_ S2A_SUMDATA2_CUS_Reserve6_13 : 40|8@1+ (1,0) [0|255] ""  PC,MBMU
 SG_ S2A_SUMDATA2_CUS_Reserve7_13 : 48|8@1+ (1,0) [0|255] ""  PC,MBMU
 SG_ S2A_SUMDATA2_CUS_Reserve8_13 : 56|8@1+ (1,0) [0|255] ""  PC,MBMU

BO_ 2339569486 S2A_SUMDATA2_CUS__14: 8 SBMU
 SG_ S2A_SUMDATA2_CUS_Reserve1_14 : 0|8@1+ (1,0) [0|255] ""  PC,MBMU
 SG_ S2A_SUMDATA2_CUS_Reserve2_14 : 8|8@1+ (1,0) [0|255] ""  PC,MBMU
 SG_ S2A_SUMDATA2_CUS_Reserve3_14 : 16|8@1+ (1,0) [0|255] ""  PC,MBMU
 SG_ S2A_SUMDATA2_CUS_Reserve4_14 : 24|8@1+ (1,0) [0|255] ""  PC,MBMU
 SG_ S2A_SUMDATA2_CUS_Reserve5_14 : 32|8@1+ (1,0) [0|255] ""  PC,MBMU
 SG_ S2A_SUMDATA2_CUS_Reserve6_14 : 40|8@1+ (1,0) [0|255] ""  PC,MBMU
 SG_ S2A_SUMDATA2_CUS_Reserve7_14 : 48|8@1+ (1,0) [0|255] ""  PC,MBMU
 SG_ S2A_SUMDATA2_CUS_Reserve8_14 : 56|8@1+ (1,0) [0|255] ""  PC,MBMU

BO_ 2339569487 S2A_SUMDATA2_CUS__15: 8 SBMU
 SG_ S2A_SUMDATA2_CUS_Reserve1_15 : 0|8@1+ (1,0) [0|255] ""  PC,MBMU
 SG_ S2A_SUMDATA2_CUS_Reserve2_15 : 8|8@1+ (1,0) [0|255] ""  PC,MBMU
 SG_ S2A_SUMDATA2_CUS_Reserve3_15 : 16|8@1+ (1,0) [0|255] ""  PC,MBMU
 SG_ S2A_SUMDATA2_CUS_Reserve4_15 : 24|8@1+ (1,0) [0|255] ""  PC,MBMU
 SG_ S2A_SUMDATA2_CUS_Reserve5_15 : 32|8@1+ (1,0) [0|255] ""  PC,MBMU
 SG_ S2A_SUMDATA2_CUS_Reserve6_15 : 40|8@1+ (1,0) [0|255] ""  PC,MBMU
 SG_ S2A_SUMDATA2_CUS_Reserve7_15 : 48|8@1+ (1,0) [0|255] ""  PC,MBMU
 SG_ S2A_SUMDATA2_CUS_Reserve8_15 : 56|8@1+ (1,0) [0|255] ""  PC,MBMU

BO_ 2339569488 S2A_SUMDATA2_CUS__16: 8 SBMU
 SG_ S2A_SUMDATA2_CUS_Reserve1_16 : 0|8@1+ (1,0) [0|255] ""  PC,MBMU
 SG_ S2A_SUMDATA2_CUS_Reserve2_16 : 8|8@1+ (1,0) [0|255] ""  PC,MBMU
 SG_ S2A_SUMDATA2_CUS_Reserve3_16 : 16|8@1+ (1,0) [0|255] ""  PC,MBMU
 SG_ S2A_SUMDATA2_CUS_Reserve4_16 : 24|8@1+ (1,0) [0|255] ""  PC,MBMU
 SG_ S2A_SUMDATA2_CUS_Reserve5_16 : 32|8@1+ (1,0) [0|255] ""  PC,MBMU
 SG_ S2A_SUMDATA2_CUS_Reserve6_16 : 40|8@1+ (1,0) [0|255] ""  PC,MBMU
 SG_ S2A_SUMDATA2_CUS_Reserve7_16 : 48|8@1+ (1,0) [0|255] ""  PC,MBMU
 SG_ S2A_SUMDATA2_CUS_Reserve8_16 : 56|8@1+ (1,0) [0|255] ""  PC,MBMU

BO_ 2339569489 S2A_SUMDATA2_CUS__17: 8 SBMU
 SG_ S2A_SUMDATA2_CUS_Reserve1_17 : 0|8@1+ (1,0) [0|255] ""  PC,MBMU
 SG_ S2A_SUMDATA2_CUS_Reserve2_17 : 8|8@1+ (1,0) [0|255] ""  PC,MBMU
 SG_ S2A_SUMDATA2_CUS_Reserve3_17 : 16|8@1+ (1,0) [0|255] ""  PC,MBMU
 SG_ S2A_SUMDATA2_CUS_Reserve4_17 : 24|8@1+ (1,0) [0|255] ""  PC,MBMU
 SG_ S2A_SUMDATA2_CUS_Reserve5_17 : 32|8@1+ (1,0) [0|255] ""  PC,MBMU
 SG_ S2A_SUMDATA2_CUS_Reserve6_17 : 40|8@1+ (1,0) [0|255] ""  PC,MBMU
 SG_ S2A_SUMDATA2_CUS_Reserve7_17 : 48|8@1+ (1,0) [0|255] ""  PC,MBMU
 SG_ S2A_SUMDATA2_CUS_Reserve8_17 : 56|8@1+ (1,0) [0|255] ""  PC,MBMU

BO_ 2339569490 S2A_SUMDATA2_CUS__18: 8 SBMU
 SG_ S2A_SUMDATA2_CUS_Reserve1_18 : 0|8@1+ (1,0) [0|255] ""  PC,MBMU
 SG_ S2A_SUMDATA2_CUS_Reserve2_18 : 8|8@1+ (1,0) [0|255] ""  PC,MBMU
 SG_ S2A_SUMDATA2_CUS_Reserve3_18 : 16|8@1+ (1,0) [0|255] ""  PC,MBMU
 SG_ S2A_SUMDATA2_CUS_Reserve4_18 : 24|8@1+ (1,0) [0|255] ""  PC,MBMU
 SG_ S2A_SUMDATA2_CUS_Reserve5_18 : 32|8@1+ (1,0) [0|255] ""  PC,MBMU
 SG_ S2A_SUMDATA2_CUS_Reserve6_18 : 40|8@1+ (1,0) [0|255] ""  PC,MBMU
 SG_ S2A_SUMDATA2_CUS_Reserve7_18 : 48|8@1+ (1,0) [0|255] ""  PC,MBMU
 SG_ S2A_SUMDATA2_CUS_Reserve8_18 : 56|8@1+ (1,0) [0|255] ""  PC,MBMU

BO_ 2339569491 S2A_SUMDATA2_CUS__19: 8 SBMU
 SG_ S2A_SUMDATA2_CUS_Reserve1_19 : 0|8@1+ (1,0) [0|255] ""  PC,MBMU
 SG_ S2A_SUMDATA2_CUS_Reserve2_19 : 8|8@1+ (1,0) [0|255] ""  PC,MBMU
 SG_ S2A_SUMDATA2_CUS_Reserve3_19 : 16|8@1+ (1,0) [0|255] ""  PC,MBMU
 SG_ S2A_SUMDATA2_CUS_Reserve4_19 : 24|8@1+ (1,0) [0|255] ""  PC,MBMU
 SG_ S2A_SUMDATA2_CUS_Reserve5_19 : 32|8@1+ (1,0) [0|255] ""  PC,MBMU
 SG_ S2A_SUMDATA2_CUS_Reserve6_19 : 40|8@1+ (1,0) [0|255] ""  PC,MBMU
 SG_ S2A_SUMDATA2_CUS_Reserve7_19 : 48|8@1+ (1,0) [0|255] ""  PC,MBMU
 SG_ S2A_SUMDATA2_CUS_Reserve8_19 : 56|8@1+ (1,0) [0|255] ""  PC,MBMU

BO_ 2339569492 S2A_SUMDATA2_CUS__20: 8 SBMU
 SG_ S2A_SUMDATA2_CUS_Reserve1_20 : 0|8@1+ (1,0) [0|255] ""  PC,MBMU
 SG_ S2A_SUMDATA2_CUS_Reserve2_20 : 8|8@1+ (1,0) [0|255] ""  PC,MBMU
 SG_ S2A_SUMDATA2_CUS_Reserve3_20 : 16|8@1+ (1,0) [0|255] ""  PC,MBMU
 SG_ S2A_SUMDATA2_CUS_Reserve4_20 : 24|8@1+ (1,0) [0|255] ""  PC,MBMU
 SG_ S2A_SUMDATA2_CUS_Reserve5_20 : 32|8@1+ (1,0) [0|255] ""  PC,MBMU
 SG_ S2A_SUMDATA2_CUS_Reserve6_20 : 40|8@1+ (1,0) [0|255] ""  PC,MBMU
 SG_ S2A_SUMDATA2_CUS_Reserve7_20 : 48|8@1+ (1,0) [0|255] ""  PC,MBMU
 SG_ S2A_SUMDATA2_CUS_Reserve8_20 : 56|8@1+ (1,0) [0|255] ""  PC,MBMU

BO_ 2339569493 S2A_SUMDATA2_CUS__21: 8 SBMU
 SG_ S2A_SUMDATA2_CUS_Reserve1_21 : 0|8@1+ (1,0) [0|255] ""  PC,MBMU
 SG_ S2A_SUMDATA2_CUS_Reserve2_21 : 8|8@1+ (1,0) [0|255] ""  PC,MBMU
 SG_ S2A_SUMDATA2_CUS_Reserve3_21 : 16|8@1+ (1,0) [0|255] ""  PC,MBMU
 SG_ S2A_SUMDATA2_CUS_Reserve4_21 : 24|8@1+ (1,0) [0|255] ""  PC,MBMU
 SG_ S2A_SUMDATA2_CUS_Reserve5_21 : 32|8@1+ (1,0) [0|255] ""  PC,MBMU
 SG_ S2A_SUMDATA2_CUS_Reserve6_21 : 40|8@1+ (1,0) [0|255] ""  PC,MBMU
 SG_ S2A_SUMDATA2_CUS_Reserve7_21 : 48|8@1+ (1,0) [0|255] ""  PC,MBMU
 SG_ S2A_SUMDATA2_CUS_Reserve8_21 : 56|8@1+ (1,0) [0|255] ""  PC,MBMU

BO_ 2339569494 S2A_SUMDATA2_CUS__22: 8 SBMU
 SG_ S2A_SUMDATA2_CUS_Reserve1_22 : 0|8@1+ (1,0) [0|255] ""  PC,MBMU
 SG_ S2A_SUMDATA2_CUS_Reserve2_22 : 8|8@1+ (1,0) [0|255] ""  PC,MBMU
 SG_ S2A_SUMDATA2_CUS_Reserve3_22 : 16|8@1+ (1,0) [0|255] ""  PC,MBMU
 SG_ S2A_SUMDATA2_CUS_Reserve4_22 : 24|8@1+ (1,0) [0|255] ""  PC,MBMU
 SG_ S2A_SUMDATA2_CUS_Reserve5_22 : 32|8@1+ (1,0) [0|255] ""  PC,MBMU
 SG_ S2A_SUMDATA2_CUS_Reserve6_22 : 40|8@1+ (1,0) [0|255] ""  PC,MBMU
 SG_ S2A_SUMDATA2_CUS_Reserve7_22 : 48|8@1+ (1,0) [0|255] ""  PC,MBMU
 SG_ S2A_SUMDATA2_CUS_Reserve8_22 : 56|8@1+ (1,0) [0|255] ""  PC,MBMU

BO_ 2339569495 S2A_SUMDATA2_CUS__23: 8 SBMU
 SG_ S2A_SUMDATA2_CUS_Reserve1_23 : 0|8@1+ (1,0) [0|255] ""  PC,MBMU
 SG_ S2A_SUMDATA2_CUS_Reserve2_23 : 8|8@1+ (1,0) [0|255] ""  PC,MBMU
 SG_ S2A_SUMDATA2_CUS_Reserve3_23 : 16|8@1+ (1,0) [0|255] ""  PC,MBMU
 SG_ S2A_SUMDATA2_CUS_Reserve4_23 : 24|8@1+ (1,0) [0|255] ""  PC,MBMU
 SG_ S2A_SUMDATA2_CUS_Reserve5_23 : 32|8@1+ (1,0) [0|255] ""  PC,MBMU
 SG_ S2A_SUMDATA2_CUS_Reserve6_23 : 40|8@1+ (1,0) [0|255] ""  PC,MBMU
 SG_ S2A_SUMDATA2_CUS_Reserve7_23 : 48|8@1+ (1,0) [0|255] ""  PC,MBMU
 SG_ S2A_SUMDATA2_CUS_Reserve8_23 : 56|8@1+ (1,0) [0|255] ""  PC,MBMU

BO_ 2339569496 S2A_SUMDATA2_CUS__24: 8 SBMU
 SG_ S2A_SUMDATA2_CUS_Reserve1_24 : 0|8@1+ (1,0) [0|255] ""  PC,MBMU
 SG_ S2A_SUMDATA2_CUS_Reserve2_24 : 8|8@1+ (1,0) [0|255] ""  PC,MBMU
 SG_ S2A_SUMDATA2_CUS_Reserve3_24 : 16|8@1+ (1,0) [0|255] ""  PC,MBMU
 SG_ S2A_SUMDATA2_CUS_Reserve4_24 : 24|8@1+ (1,0) [0|255] ""  PC,MBMU
 SG_ S2A_SUMDATA2_CUS_Reserve5_24 : 32|8@1+ (1,0) [0|255] ""  PC,MBMU
 SG_ S2A_SUMDATA2_CUS_Reserve6_24 : 40|8@1+ (1,0) [0|255] ""  PC,MBMU
 SG_ S2A_SUMDATA2_CUS_Reserve7_24 : 48|8@1+ (1,0) [0|255] ""  PC,MBMU
 SG_ S2A_SUMDATA2_CUS_Reserve8_24 : 56|8@1+ (1,0) [0|255] ""  PC,MBMU

BO_ 2339569497 S2A_SUMDATA2_CUS__25: 8 SBMU
 SG_ S2A_SUMDATA2_CUS_Reserve1_25 : 0|8@1+ (1,0) [0|255] ""  PC,MBMU
 SG_ S2A_SUMDATA2_CUS_Reserve2_25 : 8|8@1+ (1,0) [0|255] ""  PC,MBMU
 SG_ S2A_SUMDATA2_CUS_Reserve3_25 : 16|8@1+ (1,0) [0|255] ""  PC,MBMU
 SG_ S2A_SUMDATA2_CUS_Reserve4_25 : 24|8@1+ (1,0) [0|255] ""  PC,MBMU
 SG_ S2A_SUMDATA2_CUS_Reserve5_25 : 32|8@1+ (1,0) [0|255] ""  PC,MBMU
 SG_ S2A_SUMDATA2_CUS_Reserve6_25 : 40|8@1+ (1,0) [0|255] ""  PC,MBMU
 SG_ S2A_SUMDATA2_CUS_Reserve7_25 : 48|8@1+ (1,0) [0|255] ""  PC,MBMU
 SG_ S2A_SUMDATA2_CUS_Reserve8_25 : 56|8@1+ (1,0) [0|255] ""  PC,MBMU

BO_ 2339569498 S2A_SUMDATA2_CUS__26: 8 SBMU
 SG_ S2A_SUMDATA2_CUS_Reserve1_26 : 0|8@1+ (1,0) [0|255] ""  PC,MBMU
 SG_ S2A_SUMDATA2_CUS_Reserve2_26 : 8|8@1+ (1,0) [0|255] ""  PC,MBMU
 SG_ S2A_SUMDATA2_CUS_Reserve3_26 : 16|8@1+ (1,0) [0|255] ""  PC,MBMU
 SG_ S2A_SUMDATA2_CUS_Reserve4_26 : 24|8@1+ (1,0) [0|255] ""  PC,MBMU
 SG_ S2A_SUMDATA2_CUS_Reserve5_26 : 32|8@1+ (1,0) [0|255] ""  PC,MBMU
 SG_ S2A_SUMDATA2_CUS_Reserve6_26 : 40|8@1+ (1,0) [0|255] ""  PC,MBMU
 SG_ S2A_SUMDATA2_CUS_Reserve7_26 : 48|8@1+ (1,0) [0|255] ""  PC,MBMU
 SG_ S2A_SUMDATA2_CUS_Reserve8_26 : 56|8@1+ (1,0) [0|255] ""  PC,MBMU

BO_ 2339569499 S2A_SUMDATA2_CUS__27: 8 SBMU
 SG_ S2A_SUMDATA2_CUS_Reserve1_27 : 0|8@1+ (1,0) [0|255] ""  PC,MBMU
 SG_ S2A_SUMDATA2_CUS_Reserve2_27 : 8|8@1+ (1,0) [0|255] ""  PC,MBMU
 SG_ S2A_SUMDATA2_CUS_Reserve3_27 : 16|8@1+ (1,0) [0|255] ""  PC,MBMU
 SG_ S2A_SUMDATA2_CUS_Reserve4_27 : 24|8@1+ (1,0) [0|255] ""  PC,MBMU
 SG_ S2A_SUMDATA2_CUS_Reserve5_27 : 32|8@1+ (1,0) [0|255] ""  PC,MBMU
 SG_ S2A_SUMDATA2_CUS_Reserve6_27 : 40|8@1+ (1,0) [0|255] ""  PC,MBMU
 SG_ S2A_SUMDATA2_CUS_Reserve7_27 : 48|8@1+ (1,0) [0|255] ""  PC,MBMU
 SG_ S2A_SUMDATA2_CUS_Reserve8_27 : 56|8@1+ (1,0) [0|255] ""  PC,MBMU

BO_ 2339569500 S2A_SUMDATA2_CUS__28: 8 SBMU
 SG_ S2A_SUMDATA2_CUS_Reserve1_28 : 0|8@1+ (1,0) [0|255] ""  PC,MBMU
 SG_ S2A_SUMDATA2_CUS_Reserve2_28 : 8|8@1+ (1,0) [0|255] ""  PC,MBMU
 SG_ S2A_SUMDATA2_CUS_Reserve3_28 : 16|8@1+ (1,0) [0|255] ""  PC,MBMU
 SG_ S2A_SUMDATA2_CUS_Reserve4_28 : 24|8@1+ (1,0) [0|255] ""  PC,MBMU
 SG_ S2A_SUMDATA2_CUS_Reserve5_28 : 32|8@1+ (1,0) [0|255] ""  PC,MBMU
 SG_ S2A_SUMDATA2_CUS_Reserve6_28 : 40|8@1+ (1,0) [0|255] ""  PC,MBMU
 SG_ S2A_SUMDATA2_CUS_Reserve7_28 : 48|8@1+ (1,0) [0|255] ""  PC,MBMU
 SG_ S2A_SUMDATA2_CUS_Reserve8_28 : 56|8@1+ (1,0) [0|255] ""  PC,MBMU

BO_ 2339569501 S2A_SUMDATA2_CUS__29: 8 SBMU
 SG_ S2A_SUMDATA2_CUS_Reserve1_29 : 0|8@1+ (1,0) [0|255] ""  PC,MBMU
 SG_ S2A_SUMDATA2_CUS_Reserve2_29 : 8|8@1+ (1,0) [0|255] ""  PC,MBMU
 SG_ S2A_SUMDATA2_CUS_Reserve3_29 : 16|8@1+ (1,0) [0|255] ""  PC,MBMU
 SG_ S2A_SUMDATA2_CUS_Reserve4_29 : 24|8@1+ (1,0) [0|255] ""  PC,MBMU
 SG_ S2A_SUMDATA2_CUS_Reserve5_29 : 32|8@1+ (1,0) [0|255] ""  PC,MBMU
 SG_ S2A_SUMDATA2_CUS_Reserve6_29 : 40|8@1+ (1,0) [0|255] ""  PC,MBMU
 SG_ S2A_SUMDATA2_CUS_Reserve7_29 : 48|8@1+ (1,0) [0|255] ""  PC,MBMU
 SG_ S2A_SUMDATA2_CUS_Reserve8_29 : 56|8@1+ (1,0) [0|255] ""  PC,MBMU

BO_ 2339569502 S2A_SUMDATA2_CUS__30: 8 SBMU
 SG_ S2A_SUMDATA2_CUS_Reserve1_30 : 0|8@1+ (1,0) [0|255] ""  PC,MBMU
 SG_ S2A_SUMDATA2_CUS_Reserve2_30 : 8|8@1+ (1,0) [0|255] ""  PC,MBMU
 SG_ S2A_SUMDATA2_CUS_Reserve3_30 : 16|8@1+ (1,0) [0|255] ""  PC,MBMU
 SG_ S2A_SUMDATA2_CUS_Reserve4_30 : 24|8@1+ (1,0) [0|255] ""  PC,MBMU
 SG_ S2A_SUMDATA2_CUS_Reserve5_30 : 32|8@1+ (1,0) [0|255] ""  PC,MBMU
 SG_ S2A_SUMDATA2_CUS_Reserve6_30 : 40|8@1+ (1,0) [0|255] ""  PC,MBMU
 SG_ S2A_SUMDATA2_CUS_Reserve7_30 : 48|8@1+ (1,0) [0|255] ""  PC,MBMU
 SG_ S2A_SUMDATA2_CUS_Reserve8_30 : 56|8@1+ (1,0) [0|255] ""  PC,MBMU

BO_ 2339569503 S2A_SUMDATA2_CUS__31: 8 SBMU
 SG_ S2A_SUMDATA2_CUS_Reserve1_31 : 0|8@1+ (1,0) [0|255] ""  PC,MBMU
 SG_ S2A_SUMDATA2_CUS_Reserve2_31 : 8|8@1+ (1,0) [0|255] ""  PC,MBMU
 SG_ S2A_SUMDATA2_CUS_Reserve3_31 : 16|8@1+ (1,0) [0|255] ""  PC,MBMU
 SG_ S2A_SUMDATA2_CUS_Reserve4_31 : 24|8@1+ (1,0) [0|255] ""  PC,MBMU
 SG_ S2A_SUMDATA2_CUS_Reserve5_31 : 32|8@1+ (1,0) [0|255] ""  PC,MBMU
 SG_ S2A_SUMDATA2_CUS_Reserve6_31 : 40|8@1+ (1,0) [0|255] ""  PC,MBMU
 SG_ S2A_SUMDATA2_CUS_Reserve7_31 : 48|8@1+ (1,0) [0|255] ""  PC,MBMU
 SG_ S2A_SUMDATA2_CUS_Reserve8_31 : 56|8@1+ (1,0) [0|255] ""  PC,MBMU

BO_ 2339569504 S2A_SUMDATA2_CUS__32: 8 SBMU
 SG_ S2A_SUMDATA2_CUS_Reserve1_32 : 0|8@1+ (1,0) [0|255] ""  PC,MBMU
 SG_ S2A_SUMDATA2_CUS_Reserve2_32 : 8|8@1+ (1,0) [0|255] ""  PC,MBMU
 SG_ S2A_SUMDATA2_CUS_Reserve3_32 : 16|8@1+ (1,0) [0|255] ""  PC,MBMU
 SG_ S2A_SUMDATA2_CUS_Reserve4_32 : 24|8@1+ (1,0) [0|255] ""  PC,MBMU
 SG_ S2A_SUMDATA2_CUS_Reserve5_32 : 32|8@1+ (1,0) [0|255] ""  PC,MBMU
 SG_ S2A_SUMDATA2_CUS_Reserve6_32 : 40|8@1+ (1,0) [0|255] ""  PC,MBMU
 SG_ S2A_SUMDATA2_CUS_Reserve7_32 : 48|8@1+ (1,0) [0|255] ""  PC,MBMU
 SG_ S2A_SUMDATA2_CUS_Reserve8_32 : 56|8@1+ (1,0) [0|255] ""  PC,MBMU

BO_ 2339569505 S2A_SUMDATA2_CUS__33: 8 SBMU
 SG_ S2A_SUMDATA2_CUS_Reserve1_33 : 0|8@1+ (1,0) [0|255] ""  PC,MBMU
 SG_ S2A_SUMDATA2_CUS_Reserve2_33 : 8|8@1+ (1,0) [0|255] ""  PC,MBMU
 SG_ S2A_SUMDATA2_CUS_Reserve3_33 : 16|8@1+ (1,0) [0|255] ""  PC,MBMU
 SG_ S2A_SUMDATA2_CUS_Reserve4_33 : 24|8@1+ (1,0) [0|255] ""  PC,MBMU
 SG_ S2A_SUMDATA2_CUS_Reserve5_33 : 32|8@1+ (1,0) [0|255] ""  PC,MBMU
 SG_ S2A_SUMDATA2_CUS_Reserve6_33 : 40|8@1+ (1,0) [0|255] ""  PC,MBMU
 SG_ S2A_SUMDATA2_CUS_Reserve7_33 : 48|8@1+ (1,0) [0|255] ""  PC,MBMU
 SG_ S2A_SUMDATA2_CUS_Reserve8_33 : 56|8@1+ (1,0) [0|255] ""  PC,MBMU

BO_ 2339569506 S2A_SUMDATA2_CUS__34: 8 SBMU
 SG_ S2A_SUMDATA2_CUS_Reserve1_34 : 0|8@1+ (1,0) [0|255] ""  PC,MBMU
 SG_ S2A_SUMDATA2_CUS_Reserve2_34 : 8|8@1+ (1,0) [0|255] ""  PC,MBMU
 SG_ S2A_SUMDATA2_CUS_Reserve3_34 : 16|8@1+ (1,0) [0|255] ""  PC,MBMU
 SG_ S2A_SUMDATA2_CUS_Reserve4_34 : 24|8@1+ (1,0) [0|255] ""  PC,MBMU
 SG_ S2A_SUMDATA2_CUS_Reserve5_34 : 32|8@1+ (1,0) [0|255] ""  PC,MBMU
 SG_ S2A_SUMDATA2_CUS_Reserve6_34 : 40|8@1+ (1,0) [0|255] ""  PC,MBMU
 SG_ S2A_SUMDATA2_CUS_Reserve7_34 : 48|8@1+ (1,0) [0|255] ""  PC,MBMU
 SG_ S2A_SUMDATA2_CUS_Reserve8_34 : 56|8@1+ (1,0) [0|255] ""  PC,MBMU

BO_ 2339569507 S2A_SUMDATA2_CUS__35: 8 SBMU
 SG_ S2A_SUMDATA2_CUS_Reserve1_35 : 0|8@1+ (1,0) [0|255] ""  PC,MBMU
 SG_ S2A_SUMDATA2_CUS_Reserve2_35 : 8|8@1+ (1,0) [0|255] ""  PC,MBMU
 SG_ S2A_SUMDATA2_CUS_Reserve3_35 : 16|8@1+ (1,0) [0|255] ""  PC,MBMU
 SG_ S2A_SUMDATA2_CUS_Reserve4_35 : 24|8@1+ (1,0) [0|255] ""  PC,MBMU
 SG_ S2A_SUMDATA2_CUS_Reserve5_35 : 32|8@1+ (1,0) [0|255] ""  PC,MBMU
 SG_ S2A_SUMDATA2_CUS_Reserve6_35 : 40|8@1+ (1,0) [0|255] ""  PC,MBMU
 SG_ S2A_SUMDATA2_CUS_Reserve7_35 : 48|8@1+ (1,0) [0|255] ""  PC,MBMU
 SG_ S2A_SUMDATA2_CUS_Reserve8_35 : 56|8@1+ (1,0) [0|255] ""  PC,MBMU

BO_ 2339569508 S2A_SUMDATA2_CUS__36: 8 SBMU
 SG_ S2A_SUMDATA2_CUS_Reserve1_36 : 0|8@1+ (1,0) [0|255] ""  PC,MBMU
 SG_ S2A_SUMDATA2_CUS_Reserve2_36 : 8|8@1+ (1,0) [0|255] ""  PC,MBMU
 SG_ S2A_SUMDATA2_CUS_Reserve3_36 : 16|8@1+ (1,0) [0|255] ""  PC,MBMU
 SG_ S2A_SUMDATA2_CUS_Reserve4_36 : 24|8@1+ (1,0) [0|255] ""  PC,MBMU
 SG_ S2A_SUMDATA2_CUS_Reserve5_36 : 32|8@1+ (1,0) [0|255] ""  PC,MBMU
 SG_ S2A_SUMDATA2_CUS_Reserve6_36 : 40|8@1+ (1,0) [0|255] ""  PC,MBMU
 SG_ S2A_SUMDATA2_CUS_Reserve7_36 : 48|8@1+ (1,0) [0|255] ""  PC,MBMU
 SG_ S2A_SUMDATA2_CUS_Reserve8_36 : 56|8@1+ (1,0) [0|255] ""  PC,MBMU

BO_ 2339569509 S2A_SUMDATA2_CUS__37: 8 SBMU
 SG_ S2A_SUMDATA2_CUS_Reserve1_37 : 0|8@1+ (1,0) [0|255] ""  PC,MBMU
 SG_ S2A_SUMDATA2_CUS_Reserve2_37 : 8|8@1+ (1,0) [0|255] ""  PC,MBMU
 SG_ S2A_SUMDATA2_CUS_Reserve3_37 : 16|8@1+ (1,0) [0|255] ""  PC,MBMU
 SG_ S2A_SUMDATA2_CUS_Reserve4_37 : 24|8@1+ (1,0) [0|255] ""  PC,MBMU
 SG_ S2A_SUMDATA2_CUS_Reserve5_37 : 32|8@1+ (1,0) [0|255] ""  PC,MBMU
 SG_ S2A_SUMDATA2_CUS_Reserve6_37 : 40|8@1+ (1,0) [0|255] ""  PC,MBMU
 SG_ S2A_SUMDATA2_CUS_Reserve7_37 : 48|8@1+ (1,0) [0|255] ""  PC,MBMU
 SG_ S2A_SUMDATA2_CUS_Reserve8_37 : 56|8@1+ (1,0) [0|255] ""  PC,MBMU

BO_ 2339569510 S2A_SUMDATA2_CUS__38: 8 SBMU
 SG_ S2A_SUMDATA2_CUS_Reserve1_38 : 0|8@1+ (1,0) [0|255] ""  PC,MBMU
 SG_ S2A_SUMDATA2_CUS_Reserve2_38 : 8|8@1+ (1,0) [0|255] ""  PC,MBMU
 SG_ S2A_SUMDATA2_CUS_Reserve3_38 : 16|8@1+ (1,0) [0|255] ""  PC,MBMU
 SG_ S2A_SUMDATA2_CUS_Reserve4_38 : 24|8@1+ (1,0) [0|255] ""  PC,MBMU
 SG_ S2A_SUMDATA2_CUS_Reserve5_38 : 32|8@1+ (1,0) [0|255] ""  PC,MBMU
 SG_ S2A_SUMDATA2_CUS_Reserve6_38 : 40|8@1+ (1,0) [0|255] ""  PC,MBMU
 SG_ S2A_SUMDATA2_CUS_Reserve7_38 : 48|8@1+ (1,0) [0|255] ""  PC,MBMU
 SG_ S2A_SUMDATA2_CUS_Reserve8_38 : 56|8@1+ (1,0) [0|255] ""  PC,MBMU

BO_ 2339569511 S2A_SUMDATA2_CUS__39: 8 SBMU
 SG_ S2A_SUMDATA2_CUS_Reserve1_39 : 0|8@1+ (1,0) [0|255] ""  PC,MBMU
 SG_ S2A_SUMDATA2_CUS_Reserve2_39 : 8|8@1+ (1,0) [0|255] ""  PC,MBMU
 SG_ S2A_SUMDATA2_CUS_Reserve3_39 : 16|8@1+ (1,0) [0|255] ""  PC,MBMU
 SG_ S2A_SUMDATA2_CUS_Reserve4_39 : 24|8@1+ (1,0) [0|255] ""  PC,MBMU
 SG_ S2A_SUMDATA2_CUS_Reserve5_39 : 32|8@1+ (1,0) [0|255] ""  PC,MBMU
 SG_ S2A_SUMDATA2_CUS_Reserve6_39 : 40|8@1+ (1,0) [0|255] ""  PC,MBMU
 SG_ S2A_SUMDATA2_CUS_Reserve7_39 : 48|8@1+ (1,0) [0|255] ""  PC,MBMU
 SG_ S2A_SUMDATA2_CUS_Reserve8_39 : 56|8@1+ (1,0) [0|255] ""  PC,MBMU

BO_ 2339569512 S2A_SUMDATA2_CUS__40: 8 SBMU
 SG_ S2A_SUMDATA2_CUS_Reserve1_40 : 0|8@1+ (1,0) [0|255] ""  PC,MBMU
 SG_ S2A_SUMDATA2_CUS_Reserve2_40 : 8|8@1+ (1,0) [0|255] ""  PC,MBMU
 SG_ S2A_SUMDATA2_CUS_Reserve3_40 : 16|8@1+ (1,0) [0|255] ""  PC,MBMU
 SG_ S2A_SUMDATA2_CUS_Reserve4_40 : 24|8@1+ (1,0) [0|255] ""  PC,MBMU
 SG_ S2A_SUMDATA2_CUS_Reserve5_40 : 32|8@1+ (1,0) [0|255] ""  PC,MBMU
 SG_ S2A_SUMDATA2_CUS_Reserve6_40 : 40|8@1+ (1,0) [0|255] ""  PC,MBMU
 SG_ S2A_SUMDATA2_CUS_Reserve7_40 : 48|8@1+ (1,0) [0|255] ""  PC,MBMU
 SG_ S2A_SUMDATA2_CUS_Reserve8_40 : 56|8@1+ (1,0) [0|255] ""  PC,MBMU

BO_ 2339569513 S2A_SUMDATA2_CUS__41: 8 SBMU
 SG_ S2A_SUMDATA2_CUS_Reserve1_41 : 0|8@1+ (1,0) [0|255] ""  PC,MBMU
 SG_ S2A_SUMDATA2_CUS_Reserve2_41 : 8|8@1+ (1,0) [0|255] ""  PC,MBMU
 SG_ S2A_SUMDATA2_CUS_Reserve3_41 : 16|8@1+ (1,0) [0|255] ""  PC,MBMU
 SG_ S2A_SUMDATA2_CUS_Reserve4_41 : 24|8@1+ (1,0) [0|255] ""  PC,MBMU
 SG_ S2A_SUMDATA2_CUS_Reserve5_41 : 32|8@1+ (1,0) [0|255] ""  PC,MBMU
 SG_ S2A_SUMDATA2_CUS_Reserve6_41 : 40|8@1+ (1,0) [0|255] ""  PC,MBMU
 SG_ S2A_SUMDATA2_CUS_Reserve7_41 : 48|8@1+ (1,0) [0|255] ""  PC,MBMU
 SG_ S2A_SUMDATA2_CUS_Reserve8_41 : 56|8@1+ (1,0) [0|255] ""  PC,MBMU

BO_ 2339569514 S2A_SUMDATA2_CUS__42: 8 SBMU
 SG_ S2A_SUMDATA2_CUS_Reserve1_42 : 0|8@1+ (1,0) [0|255] ""  PC,MBMU
 SG_ S2A_SUMDATA2_CUS_Reserve2_42 : 8|8@1+ (1,0) [0|255] ""  PC,MBMU
 SG_ S2A_SUMDATA2_CUS_Reserve3_42 : 16|8@1+ (1,0) [0|255] ""  PC,MBMU
 SG_ S2A_SUMDATA2_CUS_Reserve4_42 : 24|8@1+ (1,0) [0|255] ""  PC,MBMU
 SG_ S2A_SUMDATA2_CUS_Reserve5_42 : 32|8@1+ (1,0) [0|255] ""  PC,MBMU
 SG_ S2A_SUMDATA2_CUS_Reserve6_42 : 40|8@1+ (1,0) [0|255] ""  PC,MBMU
 SG_ S2A_SUMDATA2_CUS_Reserve7_42 : 48|8@1+ (1,0) [0|255] ""  PC,MBMU
 SG_ S2A_SUMDATA2_CUS_Reserve8_42 : 56|8@1+ (1,0) [0|255] ""  PC,MBMU

BO_ 2339569515 S2A_SUMDATA2_CUS__43: 8 SBMU
 SG_ S2A_SUMDATA2_CUS_Reserve1_43 : 0|8@1+ (1,0) [0|255] ""  PC,MBMU
 SG_ S2A_SUMDATA2_CUS_Reserve2_43 : 8|8@1+ (1,0) [0|255] ""  PC,MBMU
 SG_ S2A_SUMDATA2_CUS_Reserve3_43 : 16|8@1+ (1,0) [0|255] ""  PC,MBMU
 SG_ S2A_SUMDATA2_CUS_Reserve4_43 : 24|8@1+ (1,0) [0|255] ""  PC,MBMU
 SG_ S2A_SUMDATA2_CUS_Reserve5_43 : 32|8@1+ (1,0) [0|255] ""  PC,MBMU
 SG_ S2A_SUMDATA2_CUS_Reserve6_43 : 40|8@1+ (1,0) [0|255] ""  PC,MBMU
 SG_ S2A_SUMDATA2_CUS_Reserve7_43 : 48|8@1+ (1,0) [0|255] ""  PC,MBMU
 SG_ S2A_SUMDATA2_CUS_Reserve8_43 : 56|8@1+ (1,0) [0|255] ""  PC,MBMU

BO_ 2339569516 S2A_SUMDATA2_CUS__44: 8 SBMU
 SG_ S2A_SUMDATA2_CUS_Reserve1_44 : 0|8@1+ (1,0) [0|255] ""  PC,MBMU
 SG_ S2A_SUMDATA2_CUS_Reserve2_44 : 8|8@1+ (1,0) [0|255] ""  PC,MBMU
 SG_ S2A_SUMDATA2_CUS_Reserve3_44 : 16|8@1+ (1,0) [0|255] ""  PC,MBMU
 SG_ S2A_SUMDATA2_CUS_Reserve4_44 : 24|8@1+ (1,0) [0|255] ""  PC,MBMU
 SG_ S2A_SUMDATA2_CUS_Reserve5_44 : 32|8@1+ (1,0) [0|255] ""  PC,MBMU
 SG_ S2A_SUMDATA2_CUS_Reserve6_44 : 40|8@1+ (1,0) [0|255] ""  PC,MBMU
 SG_ S2A_SUMDATA2_CUS_Reserve7_44 : 48|8@1+ (1,0) [0|255] ""  PC,MBMU
 SG_ S2A_SUMDATA2_CUS_Reserve8_44 : 56|8@1+ (1,0) [0|255] ""  PC,MBMU

BO_ 2339569517 S2A_SUMDATA2_CUS__45: 8 SBMU
 SG_ S2A_SUMDATA2_CUS_Reserve1_45 : 0|8@1+ (1,0) [0|255] ""  PC,MBMU
 SG_ S2A_SUMDATA2_CUS_Reserve2_45 : 8|8@1+ (1,0) [0|255] ""  PC,MBMU
 SG_ S2A_SUMDATA2_CUS_Reserve3_45 : 16|8@1+ (1,0) [0|255] ""  PC,MBMU
 SG_ S2A_SUMDATA2_CUS_Reserve4_45 : 24|8@1+ (1,0) [0|255] ""  PC,MBMU
 SG_ S2A_SUMDATA2_CUS_Reserve5_45 : 32|8@1+ (1,0) [0|255] ""  PC,MBMU
 SG_ S2A_SUMDATA2_CUS_Reserve6_45 : 40|8@1+ (1,0) [0|255] ""  PC,MBMU
 SG_ S2A_SUMDATA2_CUS_Reserve7_45 : 48|8@1+ (1,0) [0|255] ""  PC,MBMU
 SG_ S2A_SUMDATA2_CUS_Reserve8_45 : 56|8@1+ (1,0) [0|255] ""  PC,MBMU

BO_ 2339569518 S2A_SUMDATA2_CUS__46: 8 SBMU
 SG_ S2A_SUMDATA2_CUS_Reserve1_46 : 0|8@1+ (1,0) [0|255] ""  PC,MBMU
 SG_ S2A_SUMDATA2_CUS_Reserve2_46 : 8|8@1+ (1,0) [0|255] ""  PC,MBMU
 SG_ S2A_SUMDATA2_CUS_Reserve3_46 : 16|8@1+ (1,0) [0|255] ""  PC,MBMU
 SG_ S2A_SUMDATA2_CUS_Reserve4_46 : 24|8@1+ (1,0) [0|255] ""  PC,MBMU
 SG_ S2A_SUMDATA2_CUS_Reserve5_46 : 32|8@1+ (1,0) [0|255] ""  PC,MBMU
 SG_ S2A_SUMDATA2_CUS_Reserve6_46 : 40|8@1+ (1,0) [0|255] ""  PC,MBMU
 SG_ S2A_SUMDATA2_CUS_Reserve7_46 : 48|8@1+ (1,0) [0|255] ""  PC,MBMU
 SG_ S2A_SUMDATA2_CUS_Reserve8_46 : 56|8@1+ (1,0) [0|255] ""  PC,MBMU

BO_ 2339569519 S2A_SUMDATA2_CUS__47: 8 SBMU
 SG_ S2A_SUMDATA2_CUS_Reserve1_47 : 0|8@1+ (1,0) [0|255] ""  PC,MBMU
 SG_ S2A_SUMDATA2_CUS_Reserve2_47 : 8|8@1+ (1,0) [0|255] ""  PC,MBMU
 SG_ S2A_SUMDATA2_CUS_Reserve3_47 : 16|8@1+ (1,0) [0|255] ""  PC,MBMU
 SG_ S2A_SUMDATA2_CUS_Reserve4_47 : 24|8@1+ (1,0) [0|255] ""  PC,MBMU
 SG_ S2A_SUMDATA2_CUS_Reserve5_47 : 32|8@1+ (1,0) [0|255] ""  PC,MBMU
 SG_ S2A_SUMDATA2_CUS_Reserve6_47 : 40|8@1+ (1,0) [0|255] ""  PC,MBMU
 SG_ S2A_SUMDATA2_CUS_Reserve7_47 : 48|8@1+ (1,0) [0|255] ""  PC,MBMU
 SG_ S2A_SUMDATA2_CUS_Reserve8_47 : 56|8@1+ (1,0) [0|255] ""  PC,MBMU

BO_ 2339569520 S2A_SUMDATA2_CUS__48: 8 SBMU
 SG_ S2A_SUMDATA2_CUS_Reserve1_48 : 0|8@1+ (1,0) [0|255] ""  PC,MBMU
 SG_ S2A_SUMDATA2_CUS_Reserve2_48 : 8|8@1+ (1,0) [0|255] ""  PC,MBMU
 SG_ S2A_SUMDATA2_CUS_Reserve3_48 : 16|8@1+ (1,0) [0|255] ""  PC,MBMU
 SG_ S2A_SUMDATA2_CUS_Reserve4_48 : 24|8@1+ (1,0) [0|255] ""  PC,MBMU
 SG_ S2A_SUMDATA2_CUS_Reserve5_48 : 32|8@1+ (1,0) [0|255] ""  PC,MBMU
 SG_ S2A_SUMDATA2_CUS_Reserve6_48 : 40|8@1+ (1,0) [0|255] ""  PC,MBMU
 SG_ S2A_SUMDATA2_CUS_Reserve7_48 : 48|8@1+ (1,0) [0|255] ""  PC,MBMU
 SG_ S2A_SUMDATA2_CUS_Reserve8_48 : 56|8@1+ (1,0) [0|255] ""  PC,MBMU

BO_ 2339569521 S2A_SUMDATA2_CUS__49: 8 SBMU
 SG_ S2A_SUMDATA2_CUS_Reserve1_49 : 0|8@1+ (1,0) [0|255] ""  PC,MBMU
 SG_ S2A_SUMDATA2_CUS_Reserve2_49 : 8|8@1+ (1,0) [0|255] ""  PC,MBMU
 SG_ S2A_SUMDATA2_CUS_Reserve3_49 : 16|8@1+ (1,0) [0|255] ""  PC,MBMU
 SG_ S2A_SUMDATA2_CUS_Reserve4_49 : 24|8@1+ (1,0) [0|255] ""  PC,MBMU
 SG_ S2A_SUMDATA2_CUS_Reserve5_49 : 32|8@1+ (1,0) [0|255] ""  PC,MBMU
 SG_ S2A_SUMDATA2_CUS_Reserve6_49 : 40|8@1+ (1,0) [0|255] ""  PC,MBMU
 SG_ S2A_SUMDATA2_CUS_Reserve7_49 : 48|8@1+ (1,0) [0|255] ""  PC,MBMU
 SG_ S2A_SUMDATA2_CUS_Reserve8_49 : 56|8@1+ (1,0) [0|255] ""  PC,MBMU

BO_ 2339569522 S2A_SUMDATA2_CUS__50: 8 SBMU
 SG_ S2A_SUMDATA2_CUS_Reserve1_50 : 0|8@1+ (1,0) [0|255] ""  PC,MBMU
 SG_ S2A_SUMDATA2_CUS_Reserve2_50 : 8|8@1+ (1,0) [0|255] ""  PC,MBMU
 SG_ S2A_SUMDATA2_CUS_Reserve3_50 : 16|8@1+ (1,0) [0|255] ""  PC,MBMU
 SG_ S2A_SUMDATA2_CUS_Reserve4_50 : 24|8@1+ (1,0) [0|255] ""  PC,MBMU
 SG_ S2A_SUMDATA2_CUS_Reserve5_50 : 32|8@1+ (1,0) [0|255] ""  PC,MBMU
 SG_ S2A_SUMDATA2_CUS_Reserve6_50 : 40|8@1+ (1,0) [0|255] ""  PC,MBMU
 SG_ S2A_SUMDATA2_CUS_Reserve7_50 : 48|8@1+ (1,0) [0|255] ""  PC,MBMU
 SG_ S2A_SUMDATA2_CUS_Reserve8_50 : 56|8@1+ (1,0) [0|255] ""  PC,MBMU

BO_ 2339569523 S2A_SUMDATA2_CUS__51: 8 SBMU
 SG_ S2A_SUMDATA2_CUS_Reserve1_51 : 0|8@1+ (1,0) [0|255] ""  PC,MBMU
 SG_ S2A_SUMDATA2_CUS_Reserve2_51 : 8|8@1+ (1,0) [0|255] ""  PC,MBMU
 SG_ S2A_SUMDATA2_CUS_Reserve3_51 : 16|8@1+ (1,0) [0|255] ""  PC,MBMU
 SG_ S2A_SUMDATA2_CUS_Reserve4_51 : 24|8@1+ (1,0) [0|255] ""  PC,MBMU
 SG_ S2A_SUMDATA2_CUS_Reserve5_51 : 32|8@1+ (1,0) [0|255] ""  PC,MBMU
 SG_ S2A_SUMDATA2_CUS_Reserve6_51 : 40|8@1+ (1,0) [0|255] ""  PC,MBMU
 SG_ S2A_SUMDATA2_CUS_Reserve7_51 : 48|8@1+ (1,0) [0|255] ""  PC,MBMU
 SG_ S2A_SUMDATA2_CUS_Reserve8_51 : 56|8@1+ (1,0) [0|255] ""  PC,MBMU

BO_ 2339569524 S2A_SUMDATA2_CUS__52: 8 SBMU
 SG_ S2A_SUMDATA2_CUS_Reserve1_52 : 0|8@1+ (1,0) [0|255] ""  PC,MBMU
 SG_ S2A_SUMDATA2_CUS_Reserve2_52 : 8|8@1+ (1,0) [0|255] ""  PC,MBMU
 SG_ S2A_SUMDATA2_CUS_Reserve3_52 : 16|8@1+ (1,0) [0|255] ""  PC,MBMU
 SG_ S2A_SUMDATA2_CUS_Reserve4_52 : 24|8@1+ (1,0) [0|255] ""  PC,MBMU
 SG_ S2A_SUMDATA2_CUS_Reserve5_52 : 32|8@1+ (1,0) [0|255] ""  PC,MBMU
 SG_ S2A_SUMDATA2_CUS_Reserve6_52 : 40|8@1+ (1,0) [0|255] ""  PC,MBMU
 SG_ S2A_SUMDATA2_CUS_Reserve7_52 : 48|8@1+ (1,0) [0|255] ""  PC,MBMU
 SG_ S2A_SUMDATA2_CUS_Reserve8_52 : 56|8@1+ (1,0) [0|255] ""  PC,MBMU

BO_ 2339569525 S2A_SUMDATA2_CUS__53: 8 SBMU
 SG_ S2A_SUMDATA2_CUS_Reserve1_53 : 0|8@1+ (1,0) [0|255] ""  PC,MBMU
 SG_ S2A_SUMDATA2_CUS_Reserve2_53 : 8|8@1+ (1,0) [0|255] ""  PC,MBMU
 SG_ S2A_SUMDATA2_CUS_Reserve3_53 : 16|8@1+ (1,0) [0|255] ""  PC,MBMU
 SG_ S2A_SUMDATA2_CUS_Reserve4_53 : 24|8@1+ (1,0) [0|255] ""  PC,MBMU
 SG_ S2A_SUMDATA2_CUS_Reserve5_53 : 32|8@1+ (1,0) [0|255] ""  PC,MBMU
 SG_ S2A_SUMDATA2_CUS_Reserve6_53 : 40|8@1+ (1,0) [0|255] ""  PC,MBMU
 SG_ S2A_SUMDATA2_CUS_Reserve7_53 : 48|8@1+ (1,0) [0|255] ""  PC,MBMU
 SG_ S2A_SUMDATA2_CUS_Reserve8_53 : 56|8@1+ (1,0) [0|255] ""  PC,MBMU

BO_ 2339569526 S2A_SUMDATA2_CUS__54: 8 SBMU
 SG_ S2A_SUMDATA2_CUS_Reserve1_54 : 0|8@1+ (1,0) [0|255] ""  PC,MBMU
 SG_ S2A_SUMDATA2_CUS_Reserve2_54 : 8|8@1+ (1,0) [0|255] ""  PC,MBMU
 SG_ S2A_SUMDATA2_CUS_Reserve3_54 : 16|8@1+ (1,0) [0|255] ""  PC,MBMU
 SG_ S2A_SUMDATA2_CUS_Reserve4_54 : 24|8@1+ (1,0) [0|255] ""  PC,MBMU
 SG_ S2A_SUMDATA2_CUS_Reserve5_54 : 32|8@1+ (1,0) [0|255] ""  PC,MBMU
 SG_ S2A_SUMDATA2_CUS_Reserve6_54 : 40|8@1+ (1,0) [0|255] ""  PC,MBMU
 SG_ S2A_SUMDATA2_CUS_Reserve7_54 : 48|8@1+ (1,0) [0|255] ""  PC,MBMU
 SG_ S2A_SUMDATA2_CUS_Reserve8_54 : 56|8@1+ (1,0) [0|255] ""  PC,MBMU

BO_ 2339569527 S2A_SUMDATA2_CUS__55: 8 SBMU
 SG_ S2A_SUMDATA2_CUS_Reserve1_55 : 0|8@1+ (1,0) [0|255] ""  PC,MBMU
 SG_ S2A_SUMDATA2_CUS_Reserve2_55 : 8|8@1+ (1,0) [0|255] ""  PC,MBMU
 SG_ S2A_SUMDATA2_CUS_Reserve3_55 : 16|8@1+ (1,0) [0|255] ""  PC,MBMU
 SG_ S2A_SUMDATA2_CUS_Reserve4_55 : 24|8@1+ (1,0) [0|255] ""  PC,MBMU
 SG_ S2A_SUMDATA2_CUS_Reserve5_55 : 32|8@1+ (1,0) [0|255] ""  PC,MBMU
 SG_ S2A_SUMDATA2_CUS_Reserve6_55 : 40|8@1+ (1,0) [0|255] ""  PC,MBMU
 SG_ S2A_SUMDATA2_CUS_Reserve7_55 : 48|8@1+ (1,0) [0|255] ""  PC,MBMU
 SG_ S2A_SUMDATA2_CUS_Reserve8_55 : 56|8@1+ (1,0) [0|255] ""  PC,MBMU

BO_ 2339569528 S2A_SUMDATA2_CUS__56: 8 SBMU
 SG_ S2A_SUMDATA2_CUS_Reserve1_56 : 0|8@1+ (1,0) [0|255] ""  PC,MBMU
 SG_ S2A_SUMDATA2_CUS_Reserve2_56 : 8|8@1+ (1,0) [0|255] ""  PC,MBMU
 SG_ S2A_SUMDATA2_CUS_Reserve3_56 : 16|8@1+ (1,0) [0|255] ""  PC,MBMU
 SG_ S2A_SUMDATA2_CUS_Reserve4_56 : 24|8@1+ (1,0) [0|255] ""  PC,MBMU
 SG_ S2A_SUMDATA2_CUS_Reserve5_56 : 32|8@1+ (1,0) [0|255] ""  PC,MBMU
 SG_ S2A_SUMDATA2_CUS_Reserve6_56 : 40|8@1+ (1,0) [0|255] ""  PC,MBMU
 SG_ S2A_SUMDATA2_CUS_Reserve7_56 : 48|8@1+ (1,0) [0|255] ""  PC,MBMU
 SG_ S2A_SUMDATA2_CUS_Reserve8_56 : 56|8@1+ (1,0) [0|255] ""  PC,MBMU

BO_ 2339569529 S2A_SUMDATA2_CUS__57: 8 SBMU
 SG_ S2A_SUMDATA2_CUS_Reserve1_57 : 0|8@1+ (1,0) [0|255] ""  PC,MBMU
 SG_ S2A_SUMDATA2_CUS_Reserve2_57 : 8|8@1+ (1,0) [0|255] ""  PC,MBMU
 SG_ S2A_SUMDATA2_CUS_Reserve3_57 : 16|8@1+ (1,0) [0|255] ""  PC,MBMU
 SG_ S2A_SUMDATA2_CUS_Reserve4_57 : 24|8@1+ (1,0) [0|255] ""  PC,MBMU
 SG_ S2A_SUMDATA2_CUS_Reserve5_57 : 32|8@1+ (1,0) [0|255] ""  PC,MBMU
 SG_ S2A_SUMDATA2_CUS_Reserve6_57 : 40|8@1+ (1,0) [0|255] ""  PC,MBMU
 SG_ S2A_SUMDATA2_CUS_Reserve7_57 : 48|8@1+ (1,0) [0|255] ""  PC,MBMU
 SG_ S2A_SUMDATA2_CUS_Reserve8_57 : 56|8@1+ (1,0) [0|255] ""  PC,MBMU

BO_ 2339569530 S2A_SUMDATA2_CUS__58: 8 SBMU
 SG_ S2A_SUMDATA2_CUS_Reserve1_58 : 0|8@1+ (1,0) [0|255] ""  PC,MBMU
 SG_ S2A_SUMDATA2_CUS_Reserve2_58 : 8|8@1+ (1,0) [0|255] ""  PC,MBMU
 SG_ S2A_SUMDATA2_CUS_Reserve3_58 : 16|8@1+ (1,0) [0|255] ""  PC,MBMU
 SG_ S2A_SUMDATA2_CUS_Reserve4_58 : 24|8@1+ (1,0) [0|255] ""  PC,MBMU
 SG_ S2A_SUMDATA2_CUS_Reserve5_58 : 32|8@1+ (1,0) [0|255] ""  PC,MBMU
 SG_ S2A_SUMDATA2_CUS_Reserve6_58 : 40|8@1+ (1,0) [0|255] ""  PC,MBMU
 SG_ S2A_SUMDATA2_CUS_Reserve7_58 : 48|8@1+ (1,0) [0|255] ""  PC,MBMU
 SG_ S2A_SUMDATA2_CUS_Reserve8_58 : 56|8@1+ (1,0) [0|255] ""  PC,MBMU

BO_ 2339569531 S2A_SUMDATA2_CUS__59: 8 SBMU
 SG_ S2A_SUMDATA2_CUS_Reserve1_59 : 0|8@1+ (1,0) [0|255] ""  PC,MBMU
 SG_ S2A_SUMDATA2_CUS_Reserve2_59 : 8|8@1+ (1,0) [0|255] ""  PC,MBMU
 SG_ S2A_SUMDATA2_CUS_Reserve3_59 : 16|8@1+ (1,0) [0|255] ""  PC,MBMU
 SG_ S2A_SUMDATA2_CUS_Reserve4_59 : 24|8@1+ (1,0) [0|255] ""  PC,MBMU
 SG_ S2A_SUMDATA2_CUS_Reserve5_59 : 32|8@1+ (1,0) [0|255] ""  PC,MBMU
 SG_ S2A_SUMDATA2_CUS_Reserve6_59 : 40|8@1+ (1,0) [0|255] ""  PC,MBMU
 SG_ S2A_SUMDATA2_CUS_Reserve7_59 : 48|8@1+ (1,0) [0|255] ""  PC,MBMU
 SG_ S2A_SUMDATA2_CUS_Reserve8_59 : 56|8@1+ (1,0) [0|255] ""  PC,MBMU

BO_ 2339569532 S2A_SUMDATA2_CUS__60: 8 SBMU
 SG_ S2A_SUMDATA2_CUS_Reserve1_60 : 0|8@1+ (1,0) [0|255] ""  PC,MBMU
 SG_ S2A_SUMDATA2_CUS_Reserve2_60 : 8|8@1+ (1,0) [0|255] ""  PC,MBMU
 SG_ S2A_SUMDATA2_CUS_Reserve3_60 : 16|8@1+ (1,0) [0|255] ""  PC,MBMU
 SG_ S2A_SUMDATA2_CUS_Reserve4_60 : 24|8@1+ (1,0) [0|255] ""  PC,MBMU
 SG_ S2A_SUMDATA2_CUS_Reserve5_60 : 32|8@1+ (1,0) [0|255] ""  PC,MBMU
 SG_ S2A_SUMDATA2_CUS_Reserve6_60 : 40|8@1+ (1,0) [0|255] ""  PC,MBMU
 SG_ S2A_SUMDATA2_CUS_Reserve7_60 : 48|8@1+ (1,0) [0|255] ""  PC,MBMU
 SG_ S2A_SUMDATA2_CUS_Reserve8_60 : 56|8@1+ (1,0) [0|255] ""  PC,MBMU

BO_ 2339569533 S2A_SUMDATA2_CUS__61: 8 SBMU
 SG_ S2A_SUMDATA2_CUS_Reserve1_61 : 0|8@1+ (1,0) [0|255] ""  PC,MBMU
 SG_ S2A_SUMDATA2_CUS_Reserve2_61 : 8|8@1+ (1,0) [0|255] ""  PC,MBMU
 SG_ S2A_SUMDATA2_CUS_Reserve3_61 : 16|8@1+ (1,0) [0|255] ""  PC,MBMU
 SG_ S2A_SUMDATA2_CUS_Reserve4_61 : 24|8@1+ (1,0) [0|255] ""  PC,MBMU
 SG_ S2A_SUMDATA2_CUS_Reserve5_61 : 32|8@1+ (1,0) [0|255] ""  PC,MBMU
 SG_ S2A_SUMDATA2_CUS_Reserve6_61 : 40|8@1+ (1,0) [0|255] ""  PC,MBMU
 SG_ S2A_SUMDATA2_CUS_Reserve7_61 : 48|8@1+ (1,0) [0|255] ""  PC,MBMU
 SG_ S2A_SUMDATA2_CUS_Reserve8_61 : 56|8@1+ (1,0) [0|255] ""  PC,MBMU

BO_ 2339569534 S2A_SUMDATA2_CUS__62: 8 SBMU
 SG_ S2A_SUMDATA2_CUS_Reserve1_62 : 0|8@1+ (1,0) [0|255] ""  PC,MBMU
 SG_ S2A_SUMDATA2_CUS_Reserve2_62 : 8|8@1+ (1,0) [0|255] ""  PC,MBMU
 SG_ S2A_SUMDATA2_CUS_Reserve3_62 : 16|8@1+ (1,0) [0|255] ""  PC,MBMU
 SG_ S2A_SUMDATA2_CUS_Reserve4_62 : 24|8@1+ (1,0) [0|255] ""  PC,MBMU
 SG_ S2A_SUMDATA2_CUS_Reserve5_62 : 32|8@1+ (1,0) [0|255] ""  PC,MBMU
 SG_ S2A_SUMDATA2_CUS_Reserve6_62 : 40|8@1+ (1,0) [0|255] ""  PC,MBMU
 SG_ S2A_SUMDATA2_CUS_Reserve7_62 : 48|8@1+ (1,0) [0|255] ""  PC,MBMU
 SG_ S2A_SUMDATA2_CUS_Reserve8_62 : 56|8@1+ (1,0) [0|255] ""  PC,MBMU

BO_ 2339569535 S2A_SUMDATA2_CUS__63: 8 SBMU
 SG_ S2A_SUMDATA2_CUS_Reserve1_63 : 0|8@1+ (1,0) [0|255] ""  PC,MBMU
 SG_ S2A_SUMDATA2_CUS_Reserve2_63 : 8|8@1+ (1,0) [0|255] ""  PC,MBMU
 SG_ S2A_SUMDATA2_CUS_Reserve3_63 : 16|8@1+ (1,0) [0|255] ""  PC,MBMU
 SG_ S2A_SUMDATA2_CUS_Reserve4_63 : 24|8@1+ (1,0) [0|255] ""  PC,MBMU
 SG_ S2A_SUMDATA2_CUS_Reserve5_63 : 32|8@1+ (1,0) [0|255] ""  PC,MBMU
 SG_ S2A_SUMDATA2_CUS_Reserve6_63 : 40|8@1+ (1,0) [0|255] ""  PC,MBMU
 SG_ S2A_SUMDATA2_CUS_Reserve7_63 : 48|8@1+ (1,0) [0|255] ""  PC,MBMU
 SG_ S2A_SUMDATA2_CUS_Reserve8_63 : 56|8@1+ (1,0) [0|255] ""  PC,MBMU

BO_ 2339635009 S2A_SUMDATA3_CUS__01: 8 SBMU
 SG_ S2A_SUMDATA3_CUS_Reserve1_01 : 0|8@1+ (1,0) [0|255] ""  PC,MBMU
 SG_ S2A_SUMDATA3_CUS_Reserve2_01 : 8|8@1+ (1,0) [0|255] ""  PC,MBMU
 SG_ S2A_SUMDATA3_CUS_Reserve3_01 : 16|8@1+ (1,0) [0|255] ""  PC,MBMU
 SG_ S2A_SUMDATA3_CUS_Reserve4_01 : 24|8@1+ (1,0) [0|255] ""  PC,MBMU
 SG_ S2A_SUMDATA3_CUS_Reserve5_01 : 32|8@1+ (1,0) [0|255] ""  PC,MBMU
 SG_ S2A_SUMDATA3_CUS_Reserve6_01 : 40|8@1+ (1,0) [0|255] ""  PC,MBMU
 SG_ S2A_SUMDATA3_CUS_Reserve7_01 : 48|8@1+ (1,0) [0|255] ""  PC,MBMU
 SG_ S2A_SUMDATA3_CUS_Reserve8_01 : 56|8@1+ (1,0) [0|255] ""  PC,MBMU

BO_ 2339635010 S2A_SUMDATA3_CUS__02: 8 SBMU
 SG_ S2A_SUMDATA3_CUS_Reserve1_02 : 0|8@1+ (1,0) [0|255] ""  PC,MBMU
 SG_ S2A_SUMDATA3_CUS_Reserve2_02 : 8|8@1+ (1,0) [0|255] ""  PC,MBMU
 SG_ S2A_SUMDATA3_CUS_Reserve3_02 : 16|8@1+ (1,0) [0|255] ""  PC,MBMU
 SG_ S2A_SUMDATA3_CUS_Reserve4_02 : 24|8@1+ (1,0) [0|255] ""  PC,MBMU
 SG_ S2A_SUMDATA3_CUS_Reserve5_02 : 32|8@1+ (1,0) [0|255] ""  PC,MBMU
 SG_ S2A_SUMDATA3_CUS_Reserve6_02 : 40|8@1+ (1,0) [0|255] ""  PC,MBMU
 SG_ S2A_SUMDATA3_CUS_Reserve7_02 : 48|8@1+ (1,0) [0|255] ""  PC,MBMU
 SG_ S2A_SUMDATA3_CUS_Reserve8_02 : 56|8@1+ (1,0) [0|255] ""  PC,MBMU

BO_ 2339635011 S2A_SUMDATA3_CUS__03: 8 SBMU
 SG_ S2A_SUMDATA3_CUS_Reserve1_03 : 0|8@1+ (1,0) [0|255] ""  PC,MBMU
 SG_ S2A_SUMDATA3_CUS_Reserve2_03 : 8|8@1+ (1,0) [0|255] ""  PC,MBMU
 SG_ S2A_SUMDATA3_CUS_Reserve3_03 : 16|8@1+ (1,0) [0|255] ""  PC,MBMU
 SG_ S2A_SUMDATA3_CUS_Reserve4_03 : 24|8@1+ (1,0) [0|255] ""  PC,MBMU
 SG_ S2A_SUMDATA3_CUS_Reserve5_03 : 32|8@1+ (1,0) [0|255] ""  PC,MBMU
 SG_ S2A_SUMDATA3_CUS_Reserve6_03 : 40|8@1+ (1,0) [0|255] ""  PC,MBMU
 SG_ S2A_SUMDATA3_CUS_Reserve7_03 : 48|8@1+ (1,0) [0|255] ""  PC,MBMU
 SG_ S2A_SUMDATA3_CUS_Reserve8_03 : 56|8@1+ (1,0) [0|255] ""  PC,MBMU

BO_ 2339635012 S2A_SUMDATA3_CUS__04: 8 SBMU
 SG_ S2A_SUMDATA3_CUS_Reserve1_04 : 0|8@1+ (1,0) [0|255] ""  PC,MBMU
 SG_ S2A_SUMDATA3_CUS_Reserve2_04 : 8|8@1+ (1,0) [0|255] ""  PC,MBMU
 SG_ S2A_SUMDATA3_CUS_Reserve3_04 : 16|8@1+ (1,0) [0|255] ""  PC,MBMU
 SG_ S2A_SUMDATA3_CUS_Reserve4_04 : 24|8@1+ (1,0) [0|255] ""  PC,MBMU
 SG_ S2A_SUMDATA3_CUS_Reserve5_04 : 32|8@1+ (1,0) [0|255] ""  PC,MBMU
 SG_ S2A_SUMDATA3_CUS_Reserve6_04 : 40|8@1+ (1,0) [0|255] ""  PC,MBMU
 SG_ S2A_SUMDATA3_CUS_Reserve7_04 : 48|8@1+ (1,0) [0|255] ""  PC,MBMU
 SG_ S2A_SUMDATA3_CUS_Reserve8_04 : 56|8@1+ (1,0) [0|255] ""  PC,MBMU

BO_ 2339635013 S2A_SUMDATA3_CUS__05: 8 SBMU
 SG_ S2A_SUMDATA3_CUS_Reserve1_05 : 0|8@1+ (1,0) [0|255] ""  PC,MBMU
 SG_ S2A_SUMDATA3_CUS_Reserve2_05 : 8|8@1+ (1,0) [0|255] ""  PC,MBMU
 SG_ S2A_SUMDATA3_CUS_Reserve3_05 : 16|8@1+ (1,0) [0|255] ""  PC,MBMU
 SG_ S2A_SUMDATA3_CUS_Reserve4_05 : 24|8@1+ (1,0) [0|255] ""  PC,MBMU
 SG_ S2A_SUMDATA3_CUS_Reserve5_05 : 32|8@1+ (1,0) [0|255] ""  PC,MBMU
 SG_ S2A_SUMDATA3_CUS_Reserve6_05 : 40|8@1+ (1,0) [0|255] ""  PC,MBMU
 SG_ S2A_SUMDATA3_CUS_Reserve7_05 : 48|8@1+ (1,0) [0|255] ""  PC,MBMU
 SG_ S2A_SUMDATA3_CUS_Reserve8_05 : 56|8@1+ (1,0) [0|255] ""  PC,MBMU

BO_ 2339635014 S2A_SUMDATA3_CUS__06: 8 SBMU
 SG_ S2A_SUMDATA3_CUS_Reserve1_06 : 0|8@1+ (1,0) [0|255] ""  PC,MBMU
 SG_ S2A_SUMDATA3_CUS_Reserve2_06 : 8|8@1+ (1,0) [0|255] ""  PC,MBMU
 SG_ S2A_SUMDATA3_CUS_Reserve3_06 : 16|8@1+ (1,0) [0|255] ""  PC,MBMU
 SG_ S2A_SUMDATA3_CUS_Reserve4_06 : 24|8@1+ (1,0) [0|255] ""  PC,MBMU
 SG_ S2A_SUMDATA3_CUS_Reserve5_06 : 32|8@1+ (1,0) [0|255] ""  PC,MBMU
 SG_ S2A_SUMDATA3_CUS_Reserve6_06 : 40|8@1+ (1,0) [0|255] ""  PC,MBMU
 SG_ S2A_SUMDATA3_CUS_Reserve7_06 : 48|8@1+ (1,0) [0|255] ""  PC,MBMU
 SG_ S2A_SUMDATA3_CUS_Reserve8_06 : 56|8@1+ (1,0) [0|255] ""  PC,MBMU

BO_ 2339635015 S2A_SUMDATA3_CUS__07: 8 SBMU
 SG_ S2A_SUMDATA3_CUS_Reserve1_07 : 0|8@1+ (1,0) [0|255] ""  PC,MBMU
 SG_ S2A_SUMDATA3_CUS_Reserve2_07 : 8|8@1+ (1,0) [0|255] ""  PC,MBMU
 SG_ S2A_SUMDATA3_CUS_Reserve3_07 : 16|8@1+ (1,0) [0|255] ""  PC,MBMU
 SG_ S2A_SUMDATA3_CUS_Reserve4_07 : 24|8@1+ (1,0) [0|255] ""  PC,MBMU
 SG_ S2A_SUMDATA3_CUS_Reserve5_07 : 32|8@1+ (1,0) [0|255] ""  PC,MBMU
 SG_ S2A_SUMDATA3_CUS_Reserve6_07 : 40|8@1+ (1,0) [0|255] ""  PC,MBMU
 SG_ S2A_SUMDATA3_CUS_Reserve7_07 : 48|8@1+ (1,0) [0|255] ""  PC,MBMU
 SG_ S2A_SUMDATA3_CUS_Reserve8_07 : 56|8@1+ (1,0) [0|255] ""  PC,MBMU

BO_ 2339635016 S2A_SUMDATA3_CUS__08: 8 SBMU
 SG_ S2A_SUMDATA3_CUS_Reserve1_08 : 0|8@1+ (1,0) [0|255] ""  PC,MBMU
 SG_ S2A_SUMDATA3_CUS_Reserve2_08 : 8|8@1+ (1,0) [0|255] ""  PC,MBMU
 SG_ S2A_SUMDATA3_CUS_Reserve3_08 : 16|8@1+ (1,0) [0|255] ""  PC,MBMU
 SG_ S2A_SUMDATA3_CUS_Reserve4_08 : 24|8@1+ (1,0) [0|255] ""  PC,MBMU
 SG_ S2A_SUMDATA3_CUS_Reserve5_08 : 32|8@1+ (1,0) [0|255] ""  PC,MBMU
 SG_ S2A_SUMDATA3_CUS_Reserve6_08 : 40|8@1+ (1,0) [0|255] ""  PC,MBMU
 SG_ S2A_SUMDATA3_CUS_Reserve7_08 : 48|8@1+ (1,0) [0|255] ""  PC,MBMU
 SG_ S2A_SUMDATA3_CUS_Reserve8_08 : 56|8@1+ (1,0) [0|255] ""  PC,MBMU

BO_ 2339635017 S2A_SUMDATA3_CUS__09: 8 SBMU
 SG_ S2A_SUMDATA3_CUS_Reserve1_09 : 0|8@1+ (1,0) [0|255] ""  PC,MBMU
 SG_ S2A_SUMDATA3_CUS_Reserve2_09 : 8|8@1+ (1,0) [0|255] ""  PC,MBMU
 SG_ S2A_SUMDATA3_CUS_Reserve3_09 : 16|8@1+ (1,0) [0|255] ""  PC,MBMU
 SG_ S2A_SUMDATA3_CUS_Reserve4_09 : 24|8@1+ (1,0) [0|255] ""  PC,MBMU
 SG_ S2A_SUMDATA3_CUS_Reserve5_09 : 32|8@1+ (1,0) [0|255] ""  PC,MBMU
 SG_ S2A_SUMDATA3_CUS_Reserve6_09 : 40|8@1+ (1,0) [0|255] ""  PC,MBMU
 SG_ S2A_SUMDATA3_CUS_Reserve7_09 : 48|8@1+ (1,0) [0|255] ""  PC,MBMU
 SG_ S2A_SUMDATA3_CUS_Reserve8_09 : 56|8@1+ (1,0) [0|255] ""  PC,MBMU

BO_ 2339635018 S2A_SUMDATA3_CUS__10: 8 SBMU
 SG_ S2A_SUMDATA3_CUS_Reserve1_10 : 0|8@1+ (1,0) [0|255] ""  PC,MBMU
 SG_ S2A_SUMDATA3_CUS_Reserve2_10 : 8|8@1+ (1,0) [0|255] ""  PC,MBMU
 SG_ S2A_SUMDATA3_CUS_Reserve3_10 : 16|8@1+ (1,0) [0|255] ""  PC,MBMU
 SG_ S2A_SUMDATA3_CUS_Reserve4_10 : 24|8@1+ (1,0) [0|255] ""  PC,MBMU
 SG_ S2A_SUMDATA3_CUS_Reserve5_10 : 32|8@1+ (1,0) [0|255] ""  PC,MBMU
 SG_ S2A_SUMDATA3_CUS_Reserve6_10 : 40|8@1+ (1,0) [0|255] ""  PC,MBMU
 SG_ S2A_SUMDATA3_CUS_Reserve7_10 : 48|8@1+ (1,0) [0|255] ""  PC,MBMU
 SG_ S2A_SUMDATA3_CUS_Reserve8_10 : 56|8@1+ (1,0) [0|255] ""  PC,MBMU

BO_ 2339635019 S2A_SUMDATA3_CUS__11: 8 SBMU
 SG_ S2A_SUMDATA3_CUS_Reserve1_11 : 0|8@1+ (1,0) [0|255] ""  PC,MBMU
 SG_ S2A_SUMDATA3_CUS_Reserve2_11 : 8|8@1+ (1,0) [0|255] ""  PC,MBMU
 SG_ S2A_SUMDATA3_CUS_Reserve3_11 : 16|8@1+ (1,0) [0|255] ""  PC,MBMU
 SG_ S2A_SUMDATA3_CUS_Reserve4_11 : 24|8@1+ (1,0) [0|255] ""  PC,MBMU
 SG_ S2A_SUMDATA3_CUS_Reserve5_11 : 32|8@1+ (1,0) [0|255] ""  PC,MBMU
 SG_ S2A_SUMDATA3_CUS_Reserve6_11 : 40|8@1+ (1,0) [0|255] ""  PC,MBMU
 SG_ S2A_SUMDATA3_CUS_Reserve7_11 : 48|8@1+ (1,0) [0|255] ""  PC,MBMU
 SG_ S2A_SUMDATA3_CUS_Reserve8_11 : 56|8@1+ (1,0) [0|255] ""  PC,MBMU

BO_ 2339635020 S2A_SUMDATA3_CUS__12: 8 SBMU
 SG_ S2A_SUMDATA3_CUS_Reserve1_12 : 0|8@1+ (1,0) [0|255] ""  PC,MBMU
 SG_ S2A_SUMDATA3_CUS_Reserve2_12 : 8|8@1+ (1,0) [0|255] ""  PC,MBMU
 SG_ S2A_SUMDATA3_CUS_Reserve3_12 : 16|8@1+ (1,0) [0|255] ""  PC,MBMU
 SG_ S2A_SUMDATA3_CUS_Reserve4_12 : 24|8@1+ (1,0) [0|255] ""  PC,MBMU
 SG_ S2A_SUMDATA3_CUS_Reserve5_12 : 32|8@1+ (1,0) [0|255] ""  PC,MBMU
 SG_ S2A_SUMDATA3_CUS_Reserve6_12 : 40|8@1+ (1,0) [0|255] ""  PC,MBMU
 SG_ S2A_SUMDATA3_CUS_Reserve7_12 : 48|8@1+ (1,0) [0|255] ""  PC,MBMU
 SG_ S2A_SUMDATA3_CUS_Reserve8_12 : 56|8@1+ (1,0) [0|255] ""  PC,MBMU

BO_ 2339635021 S2A_SUMDATA3_CUS__13: 8 SBMU
 SG_ S2A_SUMDATA3_CUS_Reserve1_13 : 0|8@1+ (1,0) [0|255] ""  PC,MBMU
 SG_ S2A_SUMDATA3_CUS_Reserve2_13 : 8|8@1+ (1,0) [0|255] ""  PC,MBMU
 SG_ S2A_SUMDATA3_CUS_Reserve3_13 : 16|8@1+ (1,0) [0|255] ""  PC,MBMU
 SG_ S2A_SUMDATA3_CUS_Reserve4_13 : 24|8@1+ (1,0) [0|255] ""  PC,MBMU
 SG_ S2A_SUMDATA3_CUS_Reserve5_13 : 32|8@1+ (1,0) [0|255] ""  PC,MBMU
 SG_ S2A_SUMDATA3_CUS_Reserve6_13 : 40|8@1+ (1,0) [0|255] ""  PC,MBMU
 SG_ S2A_SUMDATA3_CUS_Reserve7_13 : 48|8@1+ (1,0) [0|255] ""  PC,MBMU
 SG_ S2A_SUMDATA3_CUS_Reserve8_13 : 56|8@1+ (1,0) [0|255] ""  PC,MBMU

BO_ 2339635022 S2A_SUMDATA3_CUS__14: 8 SBMU
 SG_ S2A_SUMDATA3_CUS_Reserve1_14 : 0|8@1+ (1,0) [0|255] ""  PC,MBMU
 SG_ S2A_SUMDATA3_CUS_Reserve2_14 : 8|8@1+ (1,0) [0|255] ""  PC,MBMU
 SG_ S2A_SUMDATA3_CUS_Reserve3_14 : 16|8@1+ (1,0) [0|255] ""  PC,MBMU
 SG_ S2A_SUMDATA3_CUS_Reserve4_14 : 24|8@1+ (1,0) [0|255] ""  PC,MBMU
 SG_ S2A_SUMDATA3_CUS_Reserve5_14 : 32|8@1+ (1,0) [0|255] ""  PC,MBMU
 SG_ S2A_SUMDATA3_CUS_Reserve6_14 : 40|8@1+ (1,0) [0|255] ""  PC,MBMU
 SG_ S2A_SUMDATA3_CUS_Reserve7_14 : 48|8@1+ (1,0) [0|255] ""  PC,MBMU
 SG_ S2A_SUMDATA3_CUS_Reserve8_14 : 56|8@1+ (1,0) [0|255] ""  PC,MBMU

BO_ 2339635023 S2A_SUMDATA3_CUS__15: 8 SBMU
 SG_ S2A_SUMDATA3_CUS_Reserve1_15 : 0|8@1+ (1,0) [0|255] ""  PC,MBMU
 SG_ S2A_SUMDATA3_CUS_Reserve2_15 : 8|8@1+ (1,0) [0|255] ""  PC,MBMU
 SG_ S2A_SUMDATA3_CUS_Reserve3_15 : 16|8@1+ (1,0) [0|255] ""  PC,MBMU
 SG_ S2A_SUMDATA3_CUS_Reserve4_15 : 24|8@1+ (1,0) [0|255] ""  PC,MBMU
 SG_ S2A_SUMDATA3_CUS_Reserve5_15 : 32|8@1+ (1,0) [0|255] ""  PC,MBMU
 SG_ S2A_SUMDATA3_CUS_Reserve6_15 : 40|8@1+ (1,0) [0|255] ""  PC,MBMU
 SG_ S2A_SUMDATA3_CUS_Reserve7_15 : 48|8@1+ (1,0) [0|255] ""  PC,MBMU
 SG_ S2A_SUMDATA3_CUS_Reserve8_15 : 56|8@1+ (1,0) [0|255] ""  PC,MBMU

BO_ 2339635024 S2A_SUMDATA3_CUS__16: 8 SBMU
 SG_ S2A_SUMDATA3_CUS_Reserve1_16 : 0|8@1+ (1,0) [0|255] ""  PC,MBMU
 SG_ S2A_SUMDATA3_CUS_Reserve2_16 : 8|8@1+ (1,0) [0|255] ""  PC,MBMU
 SG_ S2A_SUMDATA3_CUS_Reserve3_16 : 16|8@1+ (1,0) [0|255] ""  PC,MBMU
 SG_ S2A_SUMDATA3_CUS_Reserve4_16 : 24|8@1+ (1,0) [0|255] ""  PC,MBMU
 SG_ S2A_SUMDATA3_CUS_Reserve5_16 : 32|8@1+ (1,0) [0|255] ""  PC,MBMU
 SG_ S2A_SUMDATA3_CUS_Reserve6_16 : 40|8@1+ (1,0) [0|255] ""  PC,MBMU
 SG_ S2A_SUMDATA3_CUS_Reserve7_16 : 48|8@1+ (1,0) [0|255] ""  PC,MBMU
 SG_ S2A_SUMDATA3_CUS_Reserve8_16 : 56|8@1+ (1,0) [0|255] ""  PC,MBMU

BO_ 2339635025 S2A_SUMDATA3_CUS__17: 8 SBMU
 SG_ S2A_SUMDATA3_CUS_Reserve1_17 : 0|8@1+ (1,0) [0|255] ""  PC,MBMU
 SG_ S2A_SUMDATA3_CUS_Reserve2_17 : 8|8@1+ (1,0) [0|255] ""  PC,MBMU
 SG_ S2A_SUMDATA3_CUS_Reserve3_17 : 16|8@1+ (1,0) [0|255] ""  PC,MBMU
 SG_ S2A_SUMDATA3_CUS_Reserve4_17 : 24|8@1+ (1,0) [0|255] ""  PC,MBMU
 SG_ S2A_SUMDATA3_CUS_Reserve5_17 : 32|8@1+ (1,0) [0|255] ""  PC,MBMU
 SG_ S2A_SUMDATA3_CUS_Reserve6_17 : 40|8@1+ (1,0) [0|255] ""  PC,MBMU
 SG_ S2A_SUMDATA3_CUS_Reserve7_17 : 48|8@1+ (1,0) [0|255] ""  PC,MBMU
 SG_ S2A_SUMDATA3_CUS_Reserve8_17 : 56|8@1+ (1,0) [0|255] ""  PC,MBMU

BO_ 2339635026 S2A_SUMDATA3_CUS__18: 8 SBMU
 SG_ S2A_SUMDATA3_CUS_Reserve1_18 : 0|8@1+ (1,0) [0|255] ""  PC,MBMU
 SG_ S2A_SUMDATA3_CUS_Reserve2_18 : 8|8@1+ (1,0) [0|255] ""  PC,MBMU
 SG_ S2A_SUMDATA3_CUS_Reserve3_18 : 16|8@1+ (1,0) [0|255] ""  PC,MBMU
 SG_ S2A_SUMDATA3_CUS_Reserve4_18 : 24|8@1+ (1,0) [0|255] ""  PC,MBMU
 SG_ S2A_SUMDATA3_CUS_Reserve5_18 : 32|8@1+ (1,0) [0|255] ""  PC,MBMU
 SG_ S2A_SUMDATA3_CUS_Reserve6_18 : 40|8@1+ (1,0) [0|255] ""  PC,MBMU
 SG_ S2A_SUMDATA3_CUS_Reserve7_18 : 48|8@1+ (1,0) [0|255] ""  PC,MBMU
 SG_ S2A_SUMDATA3_CUS_Reserve8_18 : 56|8@1+ (1,0) [0|255] ""  PC,MBMU

BO_ 2339635027 S2A_SUMDATA3_CUS__19: 8 SBMU
 SG_ S2A_SUMDATA3_CUS_Reserve1_19 : 0|8@1+ (1,0) [0|255] ""  PC,MBMU
 SG_ S2A_SUMDATA3_CUS_Reserve2_19 : 8|8@1+ (1,0) [0|255] ""  PC,MBMU
 SG_ S2A_SUMDATA3_CUS_Reserve3_19 : 16|8@1+ (1,0) [0|255] ""  PC,MBMU
 SG_ S2A_SUMDATA3_CUS_Reserve4_19 : 24|8@1+ (1,0) [0|255] ""  PC,MBMU
 SG_ S2A_SUMDATA3_CUS_Reserve5_19 : 32|8@1+ (1,0) [0|255] ""  PC,MBMU
 SG_ S2A_SUMDATA3_CUS_Reserve6_19 : 40|8@1+ (1,0) [0|255] ""  PC,MBMU
 SG_ S2A_SUMDATA3_CUS_Reserve7_19 : 48|8@1+ (1,0) [0|255] ""  PC,MBMU
 SG_ S2A_SUMDATA3_CUS_Reserve8_19 : 56|8@1+ (1,0) [0|255] ""  PC,MBMU

BO_ 2339635028 S2A_SUMDATA3_CUS__20: 8 SBMU
 SG_ S2A_SUMDATA3_CUS_Reserve1_20 : 0|8@1+ (1,0) [0|255] ""  PC,MBMU
 SG_ S2A_SUMDATA3_CUS_Reserve2_20 : 8|8@1+ (1,0) [0|255] ""  PC,MBMU
 SG_ S2A_SUMDATA3_CUS_Reserve3_20 : 16|8@1+ (1,0) [0|255] ""  PC,MBMU
 SG_ S2A_SUMDATA3_CUS_Reserve4_20 : 24|8@1+ (1,0) [0|255] ""  PC,MBMU
 SG_ S2A_SUMDATA3_CUS_Reserve5_20 : 32|8@1+ (1,0) [0|255] ""  PC,MBMU
 SG_ S2A_SUMDATA3_CUS_Reserve6_20 : 40|8@1+ (1,0) [0|255] ""  PC,MBMU
 SG_ S2A_SUMDATA3_CUS_Reserve7_20 : 48|8@1+ (1,0) [0|255] ""  PC,MBMU
 SG_ S2A_SUMDATA3_CUS_Reserve8_20 : 56|8@1+ (1,0) [0|255] ""  PC,MBMU

BO_ 2339635029 S2A_SUMDATA3_CUS__21: 8 SBMU
 SG_ S2A_SUMDATA3_CUS_Reserve1_21 : 0|8@1+ (1,0) [0|255] ""  PC,MBMU
 SG_ S2A_SUMDATA3_CUS_Reserve2_21 : 8|8@1+ (1,0) [0|255] ""  PC,MBMU
 SG_ S2A_SUMDATA3_CUS_Reserve3_21 : 16|8@1+ (1,0) [0|255] ""  PC,MBMU
 SG_ S2A_SUMDATA3_CUS_Reserve4_21 : 24|8@1+ (1,0) [0|255] ""  PC,MBMU
 SG_ S2A_SUMDATA3_CUS_Reserve5_21 : 32|8@1+ (1,0) [0|255] ""  PC,MBMU
 SG_ S2A_SUMDATA3_CUS_Reserve6_21 : 40|8@1+ (1,0) [0|255] ""  PC,MBMU
 SG_ S2A_SUMDATA3_CUS_Reserve7_21 : 48|8@1+ (1,0) [0|255] ""  PC,MBMU
 SG_ S2A_SUMDATA3_CUS_Reserve8_21 : 56|8@1+ (1,0) [0|255] ""  PC,MBMU

BO_ 2339635030 S2A_SUMDATA3_CUS__22: 8 SBMU
 SG_ S2A_SUMDATA3_CUS_Reserve1_22 : 0|8@1+ (1,0) [0|255] ""  PC,MBMU
 SG_ S2A_SUMDATA3_CUS_Reserve2_22 : 8|8@1+ (1,0) [0|255] ""  PC,MBMU
 SG_ S2A_SUMDATA3_CUS_Reserve3_22 : 16|8@1+ (1,0) [0|255] ""  PC,MBMU
 SG_ S2A_SUMDATA3_CUS_Reserve4_22 : 24|8@1+ (1,0) [0|255] ""  PC,MBMU
 SG_ S2A_SUMDATA3_CUS_Reserve5_22 : 32|8@1+ (1,0) [0|255] ""  PC,MBMU
 SG_ S2A_SUMDATA3_CUS_Reserve6_22 : 40|8@1+ (1,0) [0|255] ""  PC,MBMU
 SG_ S2A_SUMDATA3_CUS_Reserve7_22 : 48|8@1+ (1,0) [0|255] ""  PC,MBMU
 SG_ S2A_SUMDATA3_CUS_Reserve8_22 : 56|8@1+ (1,0) [0|255] ""  PC,MBMU

BO_ 2339635031 S2A_SUMDATA3_CUS__23: 8 SBMU
 SG_ S2A_SUMDATA3_CUS_Reserve1_23 : 0|8@1+ (1,0) [0|255] ""  PC,MBMU
 SG_ S2A_SUMDATA3_CUS_Reserve2_23 : 8|8@1+ (1,0) [0|255] ""  PC,MBMU
 SG_ S2A_SUMDATA3_CUS_Reserve3_23 : 16|8@1+ (1,0) [0|255] ""  PC,MBMU
 SG_ S2A_SUMDATA3_CUS_Reserve4_23 : 24|8@1+ (1,0) [0|255] ""  PC,MBMU
 SG_ S2A_SUMDATA3_CUS_Reserve5_23 : 32|8@1+ (1,0) [0|255] ""  PC,MBMU
 SG_ S2A_SUMDATA3_CUS_Reserve6_23 : 40|8@1+ (1,0) [0|255] ""  PC,MBMU
 SG_ S2A_SUMDATA3_CUS_Reserve7_23 : 48|8@1+ (1,0) [0|255] ""  PC,MBMU
 SG_ S2A_SUMDATA3_CUS_Reserve8_23 : 56|8@1+ (1,0) [0|255] ""  PC,MBMU

BO_ 2339635032 S2A_SUMDATA3_CUS__24: 8 SBMU
 SG_ S2A_SUMDATA3_CUS_Reserve1_24 : 0|8@1+ (1,0) [0|255] ""  PC,MBMU
 SG_ S2A_SUMDATA3_CUS_Reserve2_24 : 8|8@1+ (1,0) [0|255] ""  PC,MBMU
 SG_ S2A_SUMDATA3_CUS_Reserve3_24 : 16|8@1+ (1,0) [0|255] ""  PC,MBMU
 SG_ S2A_SUMDATA3_CUS_Reserve4_24 : 24|8@1+ (1,0) [0|255] ""  PC,MBMU
 SG_ S2A_SUMDATA3_CUS_Reserve5_24 : 32|8@1+ (1,0) [0|255] ""  PC,MBMU
 SG_ S2A_SUMDATA3_CUS_Reserve6_24 : 40|8@1+ (1,0) [0|255] ""  PC,MBMU
 SG_ S2A_SUMDATA3_CUS_Reserve7_24 : 48|8@1+ (1,0) [0|255] ""  PC,MBMU
 SG_ S2A_SUMDATA3_CUS_Reserve8_24 : 56|8@1+ (1,0) [0|255] ""  PC,MBMU

BO_ 2339635033 S2A_SUMDATA3_CUS__25: 8 SBMU
 SG_ S2A_SUMDATA3_CUS_Reserve1_25 : 0|8@1+ (1,0) [0|255] ""  PC,MBMU
 SG_ S2A_SUMDATA3_CUS_Reserve2_25 : 8|8@1+ (1,0) [0|255] ""  PC,MBMU
 SG_ S2A_SUMDATA3_CUS_Reserve3_25 : 16|8@1+ (1,0) [0|255] ""  PC,MBMU
 SG_ S2A_SUMDATA3_CUS_Reserve4_25 : 24|8@1+ (1,0) [0|255] ""  PC,MBMU
 SG_ S2A_SUMDATA3_CUS_Reserve5_25 : 32|8@1+ (1,0) [0|255] ""  PC,MBMU
 SG_ S2A_SUMDATA3_CUS_Reserve6_25 : 40|8@1+ (1,0) [0|255] ""  PC,MBMU
 SG_ S2A_SUMDATA3_CUS_Reserve7_25 : 48|8@1+ (1,0) [0|255] ""  PC,MBMU
 SG_ S2A_SUMDATA3_CUS_Reserve8_25 : 56|8@1+ (1,0) [0|255] ""  PC,MBMU

BO_ 2339635034 S2A_SUMDATA3_CUS__26: 8 SBMU
 SG_ S2A_SUMDATA3_CUS_Reserve1_26 : 0|8@1+ (1,0) [0|255] ""  PC,MBMU
 SG_ S2A_SUMDATA3_CUS_Reserve2_26 : 8|8@1+ (1,0) [0|255] ""  PC,MBMU
 SG_ S2A_SUMDATA3_CUS_Reserve3_26 : 16|8@1+ (1,0) [0|255] ""  PC,MBMU
 SG_ S2A_SUMDATA3_CUS_Reserve4_26 : 24|8@1+ (1,0) [0|255] ""  PC,MBMU
 SG_ S2A_SUMDATA3_CUS_Reserve5_26 : 32|8@1+ (1,0) [0|255] ""  PC,MBMU
 SG_ S2A_SUMDATA3_CUS_Reserve6_26 : 40|8@1+ (1,0) [0|255] ""  PC,MBMU
 SG_ S2A_SUMDATA3_CUS_Reserve7_26 : 48|8@1+ (1,0) [0|255] ""  PC,MBMU
 SG_ S2A_SUMDATA3_CUS_Reserve8_26 : 56|8@1+ (1,0) [0|255] ""  PC,MBMU

BO_ 2339635035 S2A_SUMDATA3_CUS__27: 8 SBMU
 SG_ S2A_SUMDATA3_CUS_Reserve1_27 : 0|8@1+ (1,0) [0|255] ""  PC,MBMU
 SG_ S2A_SUMDATA3_CUS_Reserve2_27 : 8|8@1+ (1,0) [0|255] ""  PC,MBMU
 SG_ S2A_SUMDATA3_CUS_Reserve3_27 : 16|8@1+ (1,0) [0|255] ""  PC,MBMU
 SG_ S2A_SUMDATA3_CUS_Reserve4_27 : 24|8@1+ (1,0) [0|255] ""  PC,MBMU
 SG_ S2A_SUMDATA3_CUS_Reserve5_27 : 32|8@1+ (1,0) [0|255] ""  PC,MBMU
 SG_ S2A_SUMDATA3_CUS_Reserve6_27 : 40|8@1+ (1,0) [0|255] ""  PC,MBMU
 SG_ S2A_SUMDATA3_CUS_Reserve7_27 : 48|8@1+ (1,0) [0|255] ""  PC,MBMU
 SG_ S2A_SUMDATA3_CUS_Reserve8_27 : 56|8@1+ (1,0) [0|255] ""  PC,MBMU

BO_ 2339635036 S2A_SUMDATA3_CUS__28: 8 SBMU
 SG_ S2A_SUMDATA3_CUS_Reserve1_28 : 0|8@1+ (1,0) [0|255] ""  PC,MBMU
 SG_ S2A_SUMDATA3_CUS_Reserve2_28 : 8|8@1+ (1,0) [0|255] ""  PC,MBMU
 SG_ S2A_SUMDATA3_CUS_Reserve3_28 : 16|8@1+ (1,0) [0|255] ""  PC,MBMU
 SG_ S2A_SUMDATA3_CUS_Reserve4_28 : 24|8@1+ (1,0) [0|255] ""  PC,MBMU
 SG_ S2A_SUMDATA3_CUS_Reserve5_28 : 32|8@1+ (1,0) [0|255] ""  PC,MBMU
 SG_ S2A_SUMDATA3_CUS_Reserve6_28 : 40|8@1+ (1,0) [0|255] ""  PC,MBMU
 SG_ S2A_SUMDATA3_CUS_Reserve7_28 : 48|8@1+ (1,0) [0|255] ""  PC,MBMU
 SG_ S2A_SUMDATA3_CUS_Reserve8_28 : 56|8@1+ (1,0) [0|255] ""  PC,MBMU

CM_ SG_ 2333605714 S2A_HisOVtimes_18 "极限过压故障累积次数";
CM_ SG_ 2333605714 S2A_HisUVtimes_18 "极限欠压故障累积次数";
CM_ SG_ 2333605714 S2A_HisOCCtimes_18 "充电过流4级故障累积次数";
CM_ SG_ 2333605714 S2A_HisOCDtimes_18 "放电过流4级故障累积次数";
CM_ SG_ 2333605715 S2A_HisOVtimes_19 "极限过压故障累积次数";
CM_ SG_ 2333605715 S2A_HisUVtimes_19 "极限欠压故障累积次数";
CM_ SG_ 2333605715 S2A_HisOCCtimes_19 "充电过流4级故障累积次数";
CM_ SG_ 2333605715 S2A_HisOCDtimes_19 "放电过流4级故障累积次数";
CM_ SG_ 2333605716 S2A_HisOVtimes_20 "极限过压故障累积次数";
CM_ SG_ 2333605716 S2A_HisUVtimes_20 "极限欠压故障累积次数";
CM_ SG_ 2333605716 S2A_HisOCCtimes_20 "充电过流4级故障累积次数";
CM_ SG_ 2333605716 S2A_HisOCDtimes_20 "放电过流4级故障累积次数";
CM_ SG_ 2333605717 S2A_HisOVtimes_21 "极限过压故障累积次数";
CM_ SG_ 2333605717 S2A_HisUVtimes_21 "极限欠压故障累积次数";
CM_ SG_ 2333605717 S2A_HisOCCtimes_21 "充电过流4级故障累积次数";
CM_ SG_ 2333605717 S2A_HisOCDtimes_21 "放电过流4级故障累积次数";
CM_ SG_ 2333605718 S2A_HisOVtimes_22 "极限过压故障累积次数";
CM_ SG_ 2333605718 S2A_HisUVtimes_22 "极限欠压故障累积次数";
CM_ SG_ 2333605718 S2A_HisOCCtimes_22 "充电过流4级故障累积次数";
CM_ SG_ 2333605718 S2A_HisOCDtimes_22 "放电过流4级故障累积次数";
CM_ SG_ 2333605719 S2A_HisOVtimes_23 "极限过压故障累积次数";
CM_ SG_ 2333605719 S2A_HisUVtimes_23 "极限欠压故障累积次数";
CM_ SG_ 2333605719 S2A_HisOCCtimes_23 "充电过流4级故障累积次数";
CM_ SG_ 2333605719 S2A_HisOCDtimes_23 "放电过流4级故障累积次数";
CM_ SG_ 2333605720 S2A_HisOVtimes_24 "极限过压故障累积次数";
CM_ SG_ 2333605720 S2A_HisUVtimes_24 "极限欠压故障累积次数";
CM_ SG_ 2333605720 S2A_HisOCCtimes_24 "充电过流4级故障累积次数";
CM_ SG_ 2333605720 S2A_HisOCDtimes_24 "放电过流4级故障累积次数";
CM_ SG_ 2333605721 S2A_HisOVtimes_25 "极限过压故障累积次数";
CM_ SG_ 2333605721 S2A_HisUVtimes_25 "极限欠压故障累积次数";
CM_ SG_ 2333605721 S2A_HisOCCtimes_25 "充电过流4级故障累积次数";
CM_ SG_ 2333605721 S2A_HisOCDtimes_25 "放电过流4级故障累积次数";
CM_ SG_ 2333605722 S2A_HisOVtimes_26 "极限过压故障累积次数";
CM_ SG_ 2333605722 S2A_HisUVtimes_26 "极限欠压故障累积次数";
CM_ SG_ 2333605722 S2A_HisOCCtimes_26 "充电过流4级故障累积次数";
CM_ SG_ 2333605722 S2A_HisOCDtimes_26 "放电过流4级故障累积次数";
CM_ SG_ 2333605723 S2A_HisOVtimes_27 "极限过压故障累积次数";
CM_ SG_ 2333605723 S2A_HisUVtimes_27 "极限欠压故障累积次数";
CM_ SG_ 2333605723 S2A_HisOCCtimes_27 "充电过流4级故障累积次数";
CM_ SG_ 2333605723 S2A_HisOCDtimes_27 "放电过流4级故障累积次数";
CM_ SG_ 2333605724 S2A_HisOVtimes_28 "极限过压故障累积次数";
CM_ SG_ 2333605724 S2A_HisUVtimes_28 "极限欠压故障累积次数";
CM_ SG_ 2333605724 S2A_HisOCCtimes_28 "充电过流4级故障累积次数";
CM_ SG_ 2333605724 S2A_HisOCDtimes_28 "放电过流4级故障累积次数";
CM_ SG_ 2333605725 S2A_HisOVtimes_29 "极限过压故障累积次数";
CM_ SG_ 2333605725 S2A_HisUVtimes_29 "极限欠压故障累积次数";
CM_ SG_ 2333605725 S2A_HisOCCtimes_29 "充电过流4级故障累积次数";
CM_ SG_ 2333605725 S2A_HisOCDtimes_29 "放电过流4级故障累积次数";
CM_ SG_ 2333605726 S2A_HisOVtimes_30 "极限过压故障累积次数";
CM_ SG_ 2333605726 S2A_HisUVtimes_30 "极限欠压故障累积次数";
CM_ SG_ 2333605726 S2A_HisOCCtimes_30 "充电过流4级故障累积次数";
CM_ SG_ 2333605726 S2A_HisOCDtimes_30 "放电过流4级故障累积次数";
CM_ SG_ 2333605727 S2A_HisOVtimes_31 "极限过压故障累积次数";
CM_ SG_ 2333605727 S2A_HisUVtimes_31 "极限欠压故障累积次数";
CM_ SG_ 2333605727 S2A_HisOCCtimes_31 "充电过流4级故障累积次数";
CM_ SG_ 2333605727 S2A_HisOCDtimes_31 "放电过流4级故障累积次数";
CM_ SG_ 2333605728 S2A_HisOVtimes_32 "极限过压故障累积次数";
CM_ SG_ 2333605728 S2A_HisUVtimes_32 "极限欠压故障累积次数";
CM_ SG_ 2333605728 S2A_HisOCCtimes_32 "充电过流4级故障累积次数";
CM_ SG_ 2333605728 S2A_HisOCDtimes_32 "放电过流4级故障累积次数";
CM_ SG_ 2333605729 S2A_HisOVtimes_33 "极限过压故障累积次数";
CM_ SG_ 2333605729 S2A_HisUVtimes_33 "极限欠压故障累积次数";
CM_ SG_ 2333605729 S2A_HisOCCtimes_33 "充电过流4级故障累积次数";
CM_ SG_ 2333605729 S2A_HisOCDtimes_33 "放电过流4级故障累积次数";
CM_ SG_ 2333605730 S2A_HisOVtimes_34 "极限过压故障累积次数";
CM_ SG_ 2333605730 S2A_HisUVtimes_34 "极限欠压故障累积次数";
CM_ SG_ 2333605730 S2A_HisOCCtimes_34 "充电过流4级故障累积次数";
CM_ SG_ 2333605730 S2A_HisOCDtimes_34 "放电过流4级故障累积次数";
CM_ SG_ 2333605731 S2A_HisOVtimes_35 "极限过压故障累积次数";
CM_ SG_ 2333605731 S2A_HisUVtimes_35 "极限欠压故障累积次数";
CM_ SG_ 2333605731 S2A_HisOCCtimes_35 "充电过流4级故障累积次数";
CM_ SG_ 2333605731 S2A_HisOCDtimes_35 "放电过流4级故障累积次数";
CM_ SG_ 2333605732 S2A_HisOVtimes_36 "极限过压故障累积次数";
CM_ SG_ 2333605732 S2A_HisUVtimes_36 "极限欠压故障累积次数";
CM_ SG_ 2333605732 S2A_HisOCCtimes_36 "充电过流4级故障累积次数";
CM_ SG_ 2333605732 S2A_HisOCDtimes_36 "放电过流4级故障累积次数";
CM_ SG_ 2333605733 S2A_HisOVtimes_37 "极限过压故障累积次数";
CM_ SG_ 2333605733 S2A_HisUVtimes_37 "极限欠压故障累积次数";
CM_ SG_ 2333605733 S2A_HisOCCtimes_37 "充电过流4级故障累积次数";
CM_ SG_ 2333605733 S2A_HisOCDtimes_37 "放电过流4级故障累积次数";
CM_ SG_ 2333605734 S2A_HisOVtimes_38 "极限过压故障累积次数";
CM_ SG_ 2333605734 S2A_HisUVtimes_38 "极限欠压故障累积次数";
CM_ SG_ 2333605734 S2A_HisOCCtimes_38 "充电过流4级故障累积次数";
CM_ SG_ 2333605734 S2A_HisOCDtimes_38 "放电过流4级故障累积次数";
CM_ SG_ 2333605735 S2A_HisOVtimes_39 "极限过压故障累积次数";
CM_ SG_ 2333605735 S2A_HisUVtimes_39 "极限欠压故障累积次数";
CM_ SG_ 2333605735 S2A_HisOCCtimes_39 "充电过流4级故障累积次数";
CM_ SG_ 2333605735 S2A_HisOCDtimes_39 "放电过流4级故障累积次数";
CM_ SG_ 2333605736 S2A_HisOVtimes_40 "极限过压故障累积次数";
CM_ SG_ 2333605736 S2A_HisUVtimes_40 "极限欠压故障累积次数";
CM_ SG_ 2333605736 S2A_HisOCCtimes_40 "充电过流4级故障累积次数";
CM_ SG_ 2333605736 S2A_HisOCDtimes_40 "放电过流4级故障累积次数";
CM_ SG_ 2333605737 S2A_HisOVtimes_41 "极限过压故障累积次数";
CM_ SG_ 2333605737 S2A_HisUVtimes_41 "极限欠压故障累积次数";
CM_ SG_ 2333605737 S2A_HisOCCtimes_41 "充电过流4级故障累积次数";
CM_ SG_ 2333605737 S2A_HisOCDtimes_41 "放电过流4级故障累积次数";
CM_ SG_ 2333605738 S2A_HisOVtimes_42 "极限过压故障累积次数";
CM_ SG_ 2333605738 S2A_HisUVtimes_42 "极限欠压故障累积次数";
CM_ SG_ 2333605738 S2A_HisOCCtimes_42 "充电过流4级故障累积次数";
CM_ SG_ 2333605738 S2A_HisOCDtimes_42 "放电过流4级故障累积次数";
CM_ SG_ 2333605739 S2A_HisOVtimes_43 "极限过压故障累积次数";
CM_ SG_ 2333605739 S2A_HisUVtimes_43 "极限欠压故障累积次数";
CM_ SG_ 2333605739 S2A_HisOCCtimes_43 "充电过流4级故障累积次数";
CM_ SG_ 2333605739 S2A_HisOCDtimes_43 "放电过流4级故障累积次数";
CM_ SG_ 2333605740 S2A_HisOVtimes_44 "极限过压故障累积次数";
CM_ SG_ 2333605740 S2A_HisUVtimes_44 "极限欠压故障累积次数";
CM_ SG_ 2333605740 S2A_HisOCCtimes_44 "充电过流4级故障累积次数";
CM_ SG_ 2333605740 S2A_HisOCDtimes_44 "放电过流4级故障累积次数";
CM_ SG_ 2333605741 S2A_HisOVtimes_45 "极限过压故障累积次数";
CM_ SG_ 2333605741 S2A_HisUVtimes_45 "极限欠压故障累积次数";
CM_ SG_ 2333605741 S2A_HisOCCtimes_45 "充电过流4级故障累积次数";
CM_ SG_ 2333605741 S2A_HisOCDtimes_45 "放电过流4级故障累积次数";
CM_ SG_ 2333605742 S2A_HisOVtimes_46 "极限过压故障累积次数";
CM_ SG_ 2333605742 S2A_HisUVtimes_46 "极限欠压故障累积次数";
CM_ SG_ 2333605742 S2A_HisOCCtimes_46 "充电过流4级故障累积次数";
CM_ SG_ 2333605742 S2A_HisOCDtimes_46 "放电过流4级故障累积次数";
CM_ SG_ 2333605743 S2A_HisOVtimes_47 "极限过压故障累积次数";
CM_ SG_ 2333605743 S2A_HisUVtimes_47 "极限欠压故障累积次数";
CM_ SG_ 2333605743 S2A_HisOCCtimes_47 "充电过流4级故障累积次数";
CM_ SG_ 2333605743 S2A_HisOCDtimes_47 "放电过流4级故障累积次数";
CM_ SG_ 2333605744 S2A_HisOVtimes_48 "极限过压故障累积次数";
CM_ SG_ 2333605744 S2A_HisUVtimes_48 "极限欠压故障累积次数";
CM_ SG_ 2333605744 S2A_HisOCCtimes_48 "充电过流4级故障累积次数";
CM_ SG_ 2333605744 S2A_HisOCDtimes_48 "放电过流4级故障累积次数";
CM_ SG_ 2333605745 S2A_HisOVtimes_49 "极限过压故障累积次数";
CM_ SG_ 2333605745 S2A_HisUVtimes_49 "极限欠压故障累积次数";
CM_ SG_ 2333605745 S2A_HisOCCtimes_49 "充电过流4级故障累积次数";
CM_ SG_ 2333605745 S2A_HisOCDtimes_49 "放电过流4级故障累积次数";
CM_ SG_ 2333605746 S2A_HisOVtimes_50 "极限过压故障累积次数";
CM_ SG_ 2333605746 S2A_HisUVtimes_50 "极限欠压故障累积次数";
CM_ SG_ 2333605746 S2A_HisOCCtimes_50 "充电过流4级故障累积次数";
CM_ SG_ 2333605746 S2A_HisOCDtimes_50 "放电过流4级故障累积次数";
CM_ SG_ 2333605747 S2A_HisOVtimes_51 "极限过压故障累积次数";
CM_ SG_ 2333605747 S2A_HisUVtimes_51 "极限欠压故障累积次数";
CM_ SG_ 2333605747 S2A_HisOCCtimes_51 "充电过流4级故障累积次数";
CM_ SG_ 2333605747 S2A_HisOCDtimes_51 "放电过流4级故障累积次数";
CM_ SG_ 2333605748 S2A_HisOVtimes_52 "极限过压故障累积次数";
CM_ SG_ 2333605748 S2A_HisUVtimes_52 "极限欠压故障累积次数";
CM_ SG_ 2333605748 S2A_HisOCCtimes_52 "充电过流4级故障累积次数";
CM_ SG_ 2333605748 S2A_HisOCDtimes_52 "放电过流4级故障累积次数";
CM_ SG_ 2333605749 S2A_HisOVtimes_53 "极限过压故障累积次数";
CM_ SG_ 2333605749 S2A_HisUVtimes_53 "极限欠压故障累积次数";
CM_ SG_ 2333605749 S2A_HisOCCtimes_53 "充电过流4级故障累积次数";
CM_ SG_ 2333605749 S2A_HisOCDtimes_53 "放电过流4级故障累积次数";
CM_ SG_ 2333605750 S2A_HisOVtimes_54 "极限过压故障累积次数";
CM_ SG_ 2333605750 S2A_HisUVtimes_54 "极限欠压故障累积次数";
CM_ SG_ 2333605750 S2A_HisOCCtimes_54 "充电过流4级故障累积次数";
CM_ SG_ 2333605750 S2A_HisOCDtimes_54 "放电过流4级故障累积次数";
CM_ SG_ 2333605751 S2A_HisOVtimes_55 "极限过压故障累积次数";
CM_ SG_ 2333605751 S2A_HisUVtimes_55 "极限欠压故障累积次数";
CM_ SG_ 2333605751 S2A_HisOCCtimes_55 "充电过流4级故障累积次数";
CM_ SG_ 2333605751 S2A_HisOCDtimes_55 "放电过流4级故障累积次数";
CM_ SG_ 2333605752 S2A_HisOVtimes_56 "极限过压故障累积次数";
CM_ SG_ 2333605752 S2A_HisUVtimes_56 "极限欠压故障累积次数";
CM_ SG_ 2333605752 S2A_HisOCCtimes_56 "充电过流4级故障累积次数";
CM_ SG_ 2333605752 S2A_HisOCDtimes_56 "放电过流4级故障累积次数";
CM_ SG_ 2333605753 S2A_HisOVtimes_57 "极限过压故障累积次数";
CM_ SG_ 2333605753 S2A_HisUVtimes_57 "极限欠压故障累积次数";
CM_ SG_ 2333605753 S2A_HisOCCtimes_57 "充电过流4级故障累积次数";
CM_ SG_ 2333605753 S2A_HisOCDtimes_57 "放电过流4级故障累积次数";
CM_ SG_ 2333605754 S2A_HisOVtimes_58 "极限过压故障累积次数";
CM_ SG_ 2333605754 S2A_HisUVtimes_58 "极限欠压故障累积次数";
CM_ SG_ 2333605754 S2A_HisOCCtimes_58 "充电过流4级故障累积次数";
CM_ SG_ 2333605754 S2A_HisOCDtimes_58 "放电过流4级故障累积次数";
CM_ SG_ 2333605755 S2A_HisOVtimes_59 "极限过压故障累积次数";
CM_ SG_ 2333605755 S2A_HisUVtimes_59 "极限欠压故障累积次数";
CM_ SG_ 2333605755 S2A_HisOCCtimes_59 "充电过流4级故障累积次数";
CM_ SG_ 2333605755 S2A_HisOCDtimes_59 "放电过流4级故障累积次数";
CM_ SG_ 2333605756 S2A_HisOVtimes_60 "极限过压故障累积次数";
CM_ SG_ 2333605756 S2A_HisUVtimes_60 "极限欠压故障累积次数";
CM_ SG_ 2333605756 S2A_HisOCCtimes_60 "充电过流4级故障累积次数";
CM_ SG_ 2333605756 S2A_HisOCDtimes_60 "放电过流4级故障累积次数";
CM_ SG_ 2333605757 S2A_HisOVtimes_61 "极限过压故障累积次数";
CM_ SG_ 2333605757 S2A_HisUVtimes_61 "极限欠压故障累积次数";
CM_ SG_ 2333605757 S2A_HisOCCtimes_61 "充电过流4级故障累积次数";
CM_ SG_ 2333605757 S2A_HisOCDtimes_61 "放电过流4级故障累积次数";
CM_ SG_ 2333605758 S2A_HisOVtimes_62 "极限过压故障累积次数";
CM_ SG_ 2333605758 S2A_HisUVtimes_62 "极限欠压故障累积次数";
CM_ SG_ 2333605758 S2A_HisOCCtimes_62 "充电过流4级故障累积次数";
CM_ SG_ 2333605758 S2A_HisOCDtimes_62 "放电过流4级故障累积次数";
CM_ SG_ 2333605759 S2A_HisOVtimes_63 "极限过压故障累积次数";
CM_ SG_ 2333605759 S2A_HisUVtimes_63 "极限欠压故障累积次数";
CM_ SG_ 2333605759 S2A_HisOCCtimes_63 "充电过流4级故障累积次数";
CM_ SG_ 2333605759 S2A_HisOCDtimes_63 "放电过流4级故障累积次数";
CM_ SG_ 2339503937 S2A_SUMDATA1_CUS_Reserve1_01 "客户预留数据";
CM_ SG_ 2339503937 S2A_SUMDATA1_CUS_Reserve2_01 "客户预留数据";
CM_ SG_ 2339503937 S2A_SUMDATA1_CUS_Reserve3_01 "客户预留数据";
CM_ SG_ 2339503937 S2A_SUMDATA1_CUS_Reserve4_01 "客户预留数据";
CM_ SG_ 2339503937 S2A_SUMDATA1_CUS_Reserve5_01 "客户预留数据";
CM_ SG_ 2339503937 S2A_SUMDATA1_CUS_Reserve6_01 "客户预留数据";
CM_ SG_ 2339503937 S2A_SUMDATA1_CUS_Reserve7_01 "客户预留数据";
CM_ SG_ 2339503937 S2A_SUMDATA1_CUS_Reserve8_01 "客户预留数据";
CM_ SG_ 2339503938 S2A_SUMDATA1_CUS_Reserve1_02 "客户预留数据";
CM_ SG_ 2339503938 S2A_SUMDATA1_CUS_Reserve2_02 "客户预留数据";
CM_ SG_ 2339503938 S2A_SUMDATA1_CUS_Reserve3_02 "客户预留数据";
CM_ SG_ 2339503938 S2A_SUMDATA1_CUS_Reserve4_02 "客户预留数据";
CM_ SG_ 2339503938 S2A_SUMDATA1_CUS_Reserve5_02 "客户预留数据";
CM_ SG_ 2339503938 S2A_SUMDATA1_CUS_Reserve6_02 "客户预留数据";
CM_ SG_ 2339503938 S2A_SUMDATA1_CUS_Reserve7_02 "客户预留数据";
CM_ SG_ 2339503938 S2A_SUMDATA1_CUS_Reserve8_02 "客户预留数据";
CM_ SG_ 2339503939 S2A_SUMDATA1_CUS_Reserve1_03 "客户预留数据";
CM_ SG_ 2339503939 S2A_SUMDATA1_CUS_Reserve2_03 "客户预留数据";
CM_ SG_ 2339503939 S2A_SUMDATA1_CUS_Reserve3_03 "客户预留数据";
CM_ SG_ 2339503939 S2A_SUMDATA1_CUS_Reserve4_03 "客户预留数据";
CM_ SG_ 2339503939 S2A_SUMDATA1_CUS_Reserve5_03 "客户预留数据";
CM_ SG_ 2339503939 S2A_SUMDATA1_CUS_Reserve6_03 "客户预留数据";
CM_ SG_ 2339503939 S2A_SUMDATA1_CUS_Reserve7_03 "客户预留数据";
CM_ SG_ 2339503939 S2A_SUMDATA1_CUS_Reserve8_03 "客户预留数据";
CM_ SG_ 2339503940 S2A_SUMDATA1_CUS_Reserve1_04 "客户预留数据";
CM_ SG_ 2339503940 S2A_SUMDATA1_CUS_Reserve2_04 "客户预留数据";
CM_ SG_ 2339503940 S2A_SUMDATA1_CUS_Reserve3_04 "客户预留数据";
CM_ SG_ 2339503940 S2A_SUMDATA1_CUS_Reserve4_04 "客户预留数据";
CM_ SG_ 2339503940 S2A_SUMDATA1_CUS_Reserve5_04 "客户预留数据";
CM_ SG_ 2339503940 S2A_SUMDATA1_CUS_Reserve6_04 "客户预留数据";
CM_ SG_ 2339503940 S2A_SUMDATA1_CUS_Reserve7_04 "客户预留数据";
CM_ SG_ 2339503940 S2A_SUMDATA1_CUS_Reserve8_04 "客户预留数据";
CM_ SG_ 2339503941 S2A_SUMDATA1_CUS_Reserve1_05 "客户预留数据";
CM_ SG_ 2339503941 S2A_SUMDATA1_CUS_Reserve2_05 "客户预留数据";
CM_ SG_ 2339503941 S2A_SUMDATA1_CUS_Reserve3_05 "客户预留数据";
CM_ SG_ 2339503941 S2A_SUMDATA1_CUS_Reserve4_05 "客户预留数据";
CM_ SG_ 2339503941 S2A_SUMDATA1_CUS_Reserve5_05 "客户预留数据";
CM_ SG_ 2339503941 S2A_SUMDATA1_CUS_Reserve6_05 "客户预留数据";
CM_ SG_ 2339503941 S2A_SUMDATA1_CUS_Reserve7_05 "客户预留数据";
CM_ SG_ 2339503941 S2A_SUMDATA1_CUS_Reserve8_05 "客户预留数据";
CM_ SG_ 2339503942 S2A_SUMDATA1_CUS_Reserve1_06 "客户预留数据";
CM_ SG_ 2339503942 S2A_SUMDATA1_CUS_Reserve2_06 "客户预留数据";
CM_ SG_ 2339503942 S2A_SUMDATA1_CUS_Reserve3_06 "客户预留数据";
CM_ SG_ 2339503942 S2A_SUMDATA1_CUS_Reserve4_06 "客户预留数据";
CM_ SG_ 2339503942 S2A_SUMDATA1_CUS_Reserve5_06 "客户预留数据";
CM_ SG_ 2339503942 S2A_SUMDATA1_CUS_Reserve6_06 "客户预留数据";
CM_ SG_ 2339503942 S2A_SUMDATA1_CUS_Reserve7_06 "客户预留数据";
CM_ SG_ 2339503942 S2A_SUMDATA1_CUS_Reserve8_06 "客户预留数据";
CM_ SG_ 2339503943 S2A_SUMDATA1_CUS_Reserve1_07 "客户预留数据";
CM_ SG_ 2339503943 S2A_SUMDATA1_CUS_Reserve2_07 "客户预留数据";
CM_ SG_ 2339503943 S2A_SUMDATA1_CUS_Reserve3_07 "客户预留数据";
CM_ SG_ 2339503943 S2A_SUMDATA1_CUS_Reserve4_07 "客户预留数据";
CM_ SG_ 2339503943 S2A_SUMDATA1_CUS_Reserve5_07 "客户预留数据";
CM_ SG_ 2339503943 S2A_SUMDATA1_CUS_Reserve6_07 "客户预留数据";
CM_ SG_ 2339503943 S2A_SUMDATA1_CUS_Reserve7_07 "客户预留数据";
CM_ SG_ 2339503943 S2A_SUMDATA1_CUS_Reserve8_07 "客户预留数据";
CM_ SG_ 2339503944 S2A_SUMDATA1_CUS_Reserve1_08 "客户预留数据";
CM_ SG_ 2339503944 S2A_SUMDATA1_CUS_Reserve2_08 "客户预留数据";
CM_ SG_ 2339503944 S2A_SUMDATA1_CUS_Reserve3_08 "客户预留数据";
CM_ SG_ 2339503944 S2A_SUMDATA1_CUS_Reserve4_08 "客户预留数据";
CM_ SG_ 2339503944 S2A_SUMDATA1_CUS_Reserve5_08 "客户预留数据";
CM_ SG_ 2339503944 S2A_SUMDATA1_CUS_Reserve6_08 "客户预留数据";
CM_ SG_ 2339503944 S2A_SUMDATA1_CUS_Reserve7_08 "客户预留数据";
CM_ SG_ 2339503944 S2A_SUMDATA1_CUS_Reserve8_08 "客户预留数据";
CM_ SG_ 2339503945 S2A_SUMDATA1_CUS_Reserve1_09 "客户预留数据";
CM_ SG_ 2339503945 S2A_SUMDATA1_CUS_Reserve2_09 "客户预留数据";
CM_ SG_ 2339503945 S2A_SUMDATA1_CUS_Reserve3_09 "客户预留数据";
CM_ SG_ 2339503945 S2A_SUMDATA1_CUS_Reserve4_09 "客户预留数据";
CM_ SG_ 2339503945 S2A_SUMDATA1_CUS_Reserve5_09 "客户预留数据";
CM_ SG_ 2339503945 S2A_SUMDATA1_CUS_Reserve6_09 "客户预留数据";
CM_ SG_ 2339503945 S2A_SUMDATA1_CUS_Reserve7_09 "客户预留数据";
CM_ SG_ 2339503945 S2A_SUMDATA1_CUS_Reserve8_09 "客户预留数据";
CM_ SG_ 2339503946 S2A_SUMDATA1_CUS_Reserve1_10 "客户预留数据";
CM_ SG_ 2339503946 S2A_SUMDATA1_CUS_Reserve2_10 "客户预留数据";
CM_ SG_ 2339503946 S2A_SUMDATA1_CUS_Reserve3_10 "客户预留数据";
CM_ SG_ 2339503946 S2A_SUMDATA1_CUS_Reserve4_10 "客户预留数据";
CM_ SG_ 2339503946 S2A_SUMDATA1_CUS_Reserve5_10 "客户预留数据";
CM_ SG_ 2339503946 S2A_SUMDATA1_CUS_Reserve6_10 "客户预留数据";
CM_ SG_ 2339503946 S2A_SUMDATA1_CUS_Reserve7_10 "客户预留数据";
CM_ SG_ 2339503946 S2A_SUMDATA1_CUS_Reserve8_10 "客户预留数据";
CM_ SG_ 2339503947 S2A_SUMDATA1_CUS_Reserve1_11 "客户预留数据";
CM_ SG_ 2339503947 S2A_SUMDATA1_CUS_Reserve2_11 "客户预留数据";
CM_ SG_ 2339503947 S2A_SUMDATA1_CUS_Reserve3_11 "客户预留数据";
CM_ SG_ 2339503947 S2A_SUMDATA1_CUS_Reserve4_11 "客户预留数据";
CM_ SG_ 2339503947 S2A_SUMDATA1_CUS_Reserve5_11 "客户预留数据";
CM_ SG_ 2339503947 S2A_SUMDATA1_CUS_Reserve6_11 "客户预留数据";
CM_ SG_ 2339503947 S2A_SUMDATA1_CUS_Reserve7_11 "客户预留数据";
CM_ SG_ 2339503947 S2A_SUMDATA1_CUS_Reserve8_11 "客户预留数据";
CM_ SG_ 2339503948 S2A_SUMDATA1_CUS_Reserve1_12 "客户预留数据";
CM_ SG_ 2339503948 S2A_SUMDATA1_CUS_Reserve2_12 "客户预留数据";
CM_ SG_ 2339503948 S2A_SUMDATA1_CUS_Reserve3_12 "客户预留数据";
CM_ SG_ 2339503948 S2A_SUMDATA1_CUS_Reserve4_12 "客户预留数据";
CM_ SG_ 2339503948 S2A_SUMDATA1_CUS_Reserve5_12 "客户预留数据";
CM_ SG_ 2339503948 S2A_SUMDATA1_CUS_Reserve6_12 "客户预留数据";
CM_ SG_ 2339503948 S2A_SUMDATA1_CUS_Reserve7_12 "客户预留数据";
CM_ SG_ 2339503948 S2A_SUMDATA1_CUS_Reserve8_12 "客户预留数据";
CM_ SG_ 2339503949 S2A_SUMDATA1_CUS_Reserve1_13 "客户预留数据";
CM_ SG_ 2339503949 S2A_SUMDATA1_CUS_Reserve2_13 "客户预留数据";
CM_ SG_ 2339503949 S2A_SUMDATA1_CUS_Reserve3_13 "客户预留数据";
CM_ SG_ 2339503949 S2A_SUMDATA1_CUS_Reserve4_13 "客户预留数据";
CM_ SG_ 2339503949 S2A_SUMDATA1_CUS_Reserve5_13 "客户预留数据";
CM_ SG_ 2339503949 S2A_SUMDATA1_CUS_Reserve6_13 "客户预留数据";
CM_ SG_ 2339503949 S2A_SUMDATA1_CUS_Reserve7_13 "客户预留数据";
CM_ SG_ 2339503949 S2A_SUMDATA1_CUS_Reserve8_13 "客户预留数据";
CM_ SG_ 2339503950 S2A_SUMDATA1_CUS_Reserve1_14 "客户预留数据";
CM_ SG_ 2339503950 S2A_SUMDATA1_CUS_Reserve2_14 "客户预留数据";
CM_ SG_ 2339503950 S2A_SUMDATA1_CUS_Reserve3_14 "客户预留数据";
CM_ SG_ 2339503950 S2A_SUMDATA1_CUS_Reserve4_14 "客户预留数据";
CM_ SG_ 2339503950 S2A_SUMDATA1_CUS_Reserve5_14 "客户预留数据";
CM_ SG_ 2339503950 S2A_SUMDATA1_CUS_Reserve6_14 "客户预留数据";
CM_ SG_ 2339503950 S2A_SUMDATA1_CUS_Reserve7_14 "客户预留数据";
CM_ SG_ 2339503950 S2A_SUMDATA1_CUS_Reserve8_14 "客户预留数据";
CM_ SG_ 2339503951 S2A_SUMDATA1_CUS_Reserve1_15 "客户预留数据";
CM_ SG_ 2339503951 S2A_SUMDATA1_CUS_Reserve2_15 "客户预留数据";
CM_ SG_ 2339503951 S2A_SUMDATA1_CUS_Reserve3_15 "客户预留数据";
CM_ SG_ 2339503951 S2A_SUMDATA1_CUS_Reserve4_15 "客户预留数据";
CM_ SG_ 2339503951 S2A_SUMDATA1_CUS_Reserve5_15 "客户预留数据";
CM_ SG_ 2339503951 S2A_SUMDATA1_CUS_Reserve6_15 "客户预留数据";
CM_ SG_ 2339503951 S2A_SUMDATA1_CUS_Reserve7_15 "客户预留数据";
CM_ SG_ 2339503951 S2A_SUMDATA1_CUS_Reserve8_15 "客户预留数据";
CM_ SG_ 2339503952 S2A_SUMDATA1_CUS_Reserve1_16 "客户预留数据";
CM_ SG_ 2339503952 S2A_SUMDATA1_CUS_Reserve2_16 "客户预留数据";
CM_ SG_ 2339503952 S2A_SUMDATA1_CUS_Reserve3_16 "客户预留数据";
CM_ SG_ 2339503952 S2A_SUMDATA1_CUS_Reserve4_16 "客户预留数据";
CM_ SG_ 2339503952 S2A_SUMDATA1_CUS_Reserve5_16 "客户预留数据";
CM_ SG_ 2339503952 S2A_SUMDATA1_CUS_Reserve6_16 "客户预留数据";
CM_ SG_ 2339503952 S2A_SUMDATA1_CUS_Reserve7_16 "客户预留数据";
CM_ SG_ 2339503952 S2A_SUMDATA1_CUS_Reserve8_16 "客户预留数据";
CM_ SG_ 2339503953 S2A_SUMDATA1_CUS_Reserve1_17 "客户预留数据";
CM_ SG_ 2339503953 S2A_SUMDATA1_CUS_Reserve2_17 "客户预留数据";
CM_ SG_ 2339503953 S2A_SUMDATA1_CUS_Reserve3_17 "客户预留数据";
CM_ SG_ 2339503953 S2A_SUMDATA1_CUS_Reserve4_17 "客户预留数据";
CM_ SG_ 2339503953 S2A_SUMDATA1_CUS_Reserve5_17 "客户预留数据";
CM_ SG_ 2339503953 S2A_SUMDATA1_CUS_Reserve6_17 "客户预留数据";
CM_ SG_ 2339503953 S2A_SUMDATA1_CUS_Reserve7_17 "客户预留数据";
CM_ SG_ 2339503953 S2A_SUMDATA1_CUS_Reserve8_17 "客户预留数据";
CM_ SG_ 2339503954 S2A_SUMDATA1_CUS_Reserve1_18 "客户预留数据";
CM_ SG_ 2339503954 S2A_SUMDATA1_CUS_Reserve2_18 "客户预留数据";
CM_ SG_ 2339503954 S2A_SUMDATA1_CUS_Reserve3_18 "客户预留数据";
CM_ SG_ 2339503954 S2A_SUMDATA1_CUS_Reserve4_18 "客户预留数据";
CM_ SG_ 2339503954 S2A_SUMDATA1_CUS_Reserve5_18 "客户预留数据";
CM_ SG_ 2339503954 S2A_SUMDATA1_CUS_Reserve6_18 "客户预留数据";
CM_ SG_ 2339503954 S2A_SUMDATA1_CUS_Reserve7_18 "客户预留数据";
CM_ SG_ 2339503954 S2A_SUMDATA1_CUS_Reserve8_18 "客户预留数据";
CM_ SG_ 2339503955 S2A_SUMDATA1_CUS_Reserve1_19 "客户预留数据";
CM_ SG_ 2339503955 S2A_SUMDATA1_CUS_Reserve2_19 "客户预留数据";
CM_ SG_ 2339503955 S2A_SUMDATA1_CUS_Reserve3_19 "客户预留数据";
CM_ SG_ 2339503955 S2A_SUMDATA1_CUS_Reserve4_19 "客户预留数据";
CM_ SG_ 2339503955 S2A_SUMDATA1_CUS_Reserve5_19 "客户预留数据";
CM_ SG_ 2339503955 S2A_SUMDATA1_CUS_Reserve6_19 "客户预留数据";
CM_ SG_ 2339503955 S2A_SUMDATA1_CUS_Reserve7_19 "客户预留数据";
CM_ SG_ 2339503955 S2A_SUMDATA1_CUS_Reserve8_19 "客户预留数据";
CM_ SG_ 2339503956 S2A_SUMDATA1_CUS_Reserve1_20 "客户预留数据";
CM_ SG_ 2339503956 S2A_SUMDATA1_CUS_Reserve2_20 "客户预留数据";
CM_ SG_ 2339503956 S2A_SUMDATA1_CUS_Reserve3_20 "客户预留数据";
CM_ SG_ 2339503956 S2A_SUMDATA1_CUS_Reserve4_20 "客户预留数据";
CM_ SG_ 2339503956 S2A_SUMDATA1_CUS_Reserve5_20 "客户预留数据";
CM_ SG_ 2339503956 S2A_SUMDATA1_CUS_Reserve6_20 "客户预留数据";
CM_ SG_ 2339503956 S2A_SUMDATA1_CUS_Reserve7_20 "客户预留数据";
CM_ SG_ 2339503956 S2A_SUMDATA1_CUS_Reserve8_20 "客户预留数据";
CM_ SG_ 2339503957 S2A_SUMDATA1_CUS_Reserve1_21 "客户预留数据";
CM_ SG_ 2339503957 S2A_SUMDATA1_CUS_Reserve2_21 "客户预留数据";
CM_ SG_ 2339503957 S2A_SUMDATA1_CUS_Reserve3_21 "客户预留数据";
CM_ SG_ 2339503957 S2A_SUMDATA1_CUS_Reserve4_21 "客户预留数据";
CM_ SG_ 2339503957 S2A_SUMDATA1_CUS_Reserve5_21 "客户预留数据";
CM_ SG_ 2339503957 S2A_SUMDATA1_CUS_Reserve6_21 "客户预留数据";
CM_ SG_ 2339503957 S2A_SUMDATA1_CUS_Reserve7_21 "客户预留数据";
CM_ SG_ 2339503957 S2A_SUMDATA1_CUS_Reserve8_21 "客户预留数据";
CM_ SG_ 2339503958 S2A_SUMDATA1_CUS_Reserve1_22 "客户预留数据";
CM_ SG_ 2339503958 S2A_SUMDATA1_CUS_Reserve2_22 "客户预留数据";
CM_ SG_ 2339503958 S2A_SUMDATA1_CUS_Reserve3_22 "客户预留数据";
CM_ SG_ 2339503958 S2A_SUMDATA1_CUS_Reserve4_22 "客户预留数据";
CM_ SG_ 2339503958 S2A_SUMDATA1_CUS_Reserve5_22 "客户预留数据";
CM_ SG_ 2339503958 S2A_SUMDATA1_CUS_Reserve6_22 "客户预留数据";
CM_ SG_ 2339503958 S2A_SUMDATA1_CUS_Reserve7_22 "客户预留数据";
CM_ SG_ 2339503958 S2A_SUMDATA1_CUS_Reserve8_22 "客户预留数据";
CM_ SG_ 2339503959 S2A_SUMDATA1_CUS_Reserve1_23 "客户预留数据";
CM_ SG_ 2339503959 S2A_SUMDATA1_CUS_Reserve2_23 "客户预留数据";
CM_ SG_ 2339503959 S2A_SUMDATA1_CUS_Reserve3_23 "客户预留数据";
CM_ SG_ 2339503959 S2A_SUMDATA1_CUS_Reserve4_23 "客户预留数据";
CM_ SG_ 2339503959 S2A_SUMDATA1_CUS_Reserve5_23 "客户预留数据";
CM_ SG_ 2339503959 S2A_SUMDATA1_CUS_Reserve6_23 "客户预留数据";
CM_ SG_ 2339503959 S2A_SUMDATA1_CUS_Reserve7_23 "客户预留数据";
CM_ SG_ 2339503959 S2A_SUMDATA1_CUS_Reserve8_23 "客户预留数据";
CM_ SG_ 2339503960 S2A_SUMDATA1_CUS_Reserve1_24 "客户预留数据";
CM_ SG_ 2339503960 S2A_SUMDATA1_CUS_Reserve2_24 "客户预留数据";
CM_ SG_ 2339503960 S2A_SUMDATA1_CUS_Reserve3_24 "客户预留数据";
CM_ SG_ 2339503960 S2A_SUMDATA1_CUS_Reserve4_24 "客户预留数据";
CM_ SG_ 2339503960 S2A_SUMDATA1_CUS_Reserve5_24 "客户预留数据";
CM_ SG_ 2339503960 S2A_SUMDATA1_CUS_Reserve6_24 "客户预留数据";
CM_ SG_ 2339503960 S2A_SUMDATA1_CUS_Reserve7_24 "客户预留数据";
CM_ SG_ 2339503960 S2A_SUMDATA1_CUS_Reserve8_24 "客户预留数据";
CM_ SG_ 2339503961 S2A_SUMDATA1_CUS_Reserve1_25 "客户预留数据";
CM_ SG_ 2339503961 S2A_SUMDATA1_CUS_Reserve2_25 "客户预留数据";
CM_ SG_ 2339503961 S2A_SUMDATA1_CUS_Reserve3_25 "客户预留数据";
CM_ SG_ 2339503961 S2A_SUMDATA1_CUS_Reserve4_25 "客户预留数据";
CM_ SG_ 2339503961 S2A_SUMDATA1_CUS_Reserve5_25 "客户预留数据";
CM_ SG_ 2339503961 S2A_SUMDATA1_CUS_Reserve6_25 "客户预留数据";
CM_ SG_ 2339503961 S2A_SUMDATA1_CUS_Reserve7_25 "客户预留数据";
CM_ SG_ 2339503961 S2A_SUMDATA1_CUS_Reserve8_25 "客户预留数据";
CM_ SG_ 2339503962 S2A_SUMDATA1_CUS_Reserve1_26 "客户预留数据";
CM_ SG_ 2339503962 S2A_SUMDATA1_CUS_Reserve2_26 "客户预留数据";
CM_ SG_ 2339503962 S2A_SUMDATA1_CUS_Reserve3_26 "客户预留数据";
CM_ SG_ 2339503962 S2A_SUMDATA1_CUS_Reserve4_26 "客户预留数据";
CM_ SG_ 2339503962 S2A_SUMDATA1_CUS_Reserve5_26 "客户预留数据";
CM_ SG_ 2339503962 S2A_SUMDATA1_CUS_Reserve6_26 "客户预留数据";
CM_ SG_ 2339503962 S2A_SUMDATA1_CUS_Reserve7_26 "客户预留数据";
CM_ SG_ 2339503962 S2A_SUMDATA1_CUS_Reserve8_26 "客户预留数据";
CM_ SG_ 2339503963 S2A_SUMDATA1_CUS_Reserve1_27 "客户预留数据";
CM_ SG_ 2339503963 S2A_SUMDATA1_CUS_Reserve2_27 "客户预留数据";
CM_ SG_ 2339503963 S2A_SUMDATA1_CUS_Reserve3_27 "客户预留数据";
CM_ SG_ 2339503963 S2A_SUMDATA1_CUS_Reserve4_27 "客户预留数据";
CM_ SG_ 2339503963 S2A_SUMDATA1_CUS_Reserve5_27 "客户预留数据";
CM_ SG_ 2339503963 S2A_SUMDATA1_CUS_Reserve6_27 "客户预留数据";
CM_ SG_ 2339503963 S2A_SUMDATA1_CUS_Reserve7_27 "客户预留数据";
CM_ SG_ 2339503963 S2A_SUMDATA1_CUS_Reserve8_27 "客户预留数据";
CM_ SG_ 2339503964 S2A_SUMDATA1_CUS_Reserve1_28 "客户预留数据";
CM_ SG_ 2339503964 S2A_SUMDATA1_CUS_Reserve2_28 "客户预留数据";
CM_ SG_ 2339503964 S2A_SUMDATA1_CUS_Reserve3_28 "客户预留数据";
CM_ SG_ 2339503964 S2A_SUMDATA1_CUS_Reserve4_28 "客户预留数据";
CM_ SG_ 2339503964 S2A_SUMDATA1_CUS_Reserve5_28 "客户预留数据";
CM_ SG_ 2339503964 S2A_SUMDATA1_CUS_Reserve6_28 "客户预留数据";
CM_ SG_ 2339503964 S2A_SUMDATA1_CUS_Reserve7_28 "客户预留数据";
CM_ SG_ 2339503964 S2A_SUMDATA1_CUS_Reserve8_28 "客户预留数据";
CM_ SG_ 2339503965 S2A_SUMDATA1_CUS_Reserve1_29 "客户预留数据";
CM_ SG_ 2339503965 S2A_SUMDATA1_CUS_Reserve2_29 "客户预留数据";
CM_ SG_ 2339503965 S2A_SUMDATA1_CUS_Reserve3_29 "客户预留数据";
CM_ SG_ 2339503965 S2A_SUMDATA1_CUS_Reserve4_29 "客户预留数据";
CM_ SG_ 2339503965 S2A_SUMDATA1_CUS_Reserve5_29 "客户预留数据";
CM_ SG_ 2339503965 S2A_SUMDATA1_CUS_Reserve6_29 "客户预留数据";
CM_ SG_ 2339503965 S2A_SUMDATA1_CUS_Reserve7_29 "客户预留数据";
CM_ SG_ 2339503965 S2A_SUMDATA1_CUS_Reserve8_29 "客户预留数据";
CM_ SG_ 2339503966 S2A_SUMDATA1_CUS_Reserve1_30 "客户预留数据";
CM_ SG_ 2339503966 S2A_SUMDATA1_CUS_Reserve2_30 "客户预留数据";
CM_ SG_ 2339503966 S2A_SUMDATA1_CUS_Reserve3_30 "客户预留数据";
CM_ SG_ 2339503966 S2A_SUMDATA1_CUS_Reserve4_30 "客户预留数据";
CM_ SG_ 2339503966 S2A_SUMDATA1_CUS_Reserve5_30 "客户预留数据";
CM_ SG_ 2339503966 S2A_SUMDATA1_CUS_Reserve6_30 "客户预留数据";
CM_ SG_ 2339503966 S2A_SUMDATA1_CUS_Reserve7_30 "客户预留数据";
CM_ SG_ 2339503966 S2A_SUMDATA1_CUS_Reserve8_30 "客户预留数据";
CM_ SG_ 2339503967 S2A_SUMDATA1_CUS_Reserve1_31 "客户预留数据";
CM_ SG_ 2339503967 S2A_SUMDATA1_CUS_Reserve2_31 "客户预留数据";
CM_ SG_ 2339503967 S2A_SUMDATA1_CUS_Reserve3_31 "客户预留数据";
CM_ SG_ 2339503967 S2A_SUMDATA1_CUS_Reserve4_31 "客户预留数据";
CM_ SG_ 2339503967 S2A_SUMDATA1_CUS_Reserve5_31 "客户预留数据";
CM_ SG_ 2339503967 S2A_SUMDATA1_CUS_Reserve6_31 "客户预留数据";
CM_ SG_ 2339503967 S2A_SUMDATA1_CUS_Reserve7_31 "客户预留数据";
CM_ SG_ 2339503967 S2A_SUMDATA1_CUS_Reserve8_31 "客户预留数据";
CM_ SG_ 2339503968 S2A_SUMDATA1_CUS_Reserve1_32 "客户预留数据";
CM_ SG_ 2339503968 S2A_SUMDATA1_CUS_Reserve2_32 "客户预留数据";
CM_ SG_ 2339503968 S2A_SUMDATA1_CUS_Reserve3_32 "客户预留数据";
CM_ SG_ 2339503968 S2A_SUMDATA1_CUS_Reserve4_32 "客户预留数据";
CM_ SG_ 2339503968 S2A_SUMDATA1_CUS_Reserve5_32 "客户预留数据";
CM_ SG_ 2339503968 S2A_SUMDATA1_CUS_Reserve6_32 "客户预留数据";
CM_ SG_ 2339503968 S2A_SUMDATA1_CUS_Reserve7_32 "客户预留数据";
CM_ SG_ 2339503968 S2A_SUMDATA1_CUS_Reserve8_32 "客户预留数据";
CM_ SG_ 2339503969 S2A_SUMDATA1_CUS_Reserve1_33 "客户预留数据";
CM_ SG_ 2339503969 S2A_SUMDATA1_CUS_Reserve2_33 "客户预留数据";
CM_ SG_ 2339503969 S2A_SUMDATA1_CUS_Reserve3_33 "客户预留数据";
CM_ SG_ 2339503969 S2A_SUMDATA1_CUS_Reserve4_33 "客户预留数据";
CM_ SG_ 2339503969 S2A_SUMDATA1_CUS_Reserve5_33 "客户预留数据";
CM_ SG_ 2339503969 S2A_SUMDATA1_CUS_Reserve6_33 "客户预留数据";
CM_ SG_ 2339503969 S2A_SUMDATA1_CUS_Reserve7_33 "客户预留数据";
CM_ SG_ 2339503969 S2A_SUMDATA1_CUS_Reserve8_33 "客户预留数据";
CM_ SG_ 2339503970 S2A_SUMDATA1_CUS_Reserve1_34 "客户预留数据";
CM_ SG_ 2339503970 S2A_SUMDATA1_CUS_Reserve2_34 "客户预留数据";
CM_ SG_ 2339503970 S2A_SUMDATA1_CUS_Reserve3_34 "客户预留数据";
CM_ SG_ 2339503970 S2A_SUMDATA1_CUS_Reserve4_34 "客户预留数据";
CM_ SG_ 2339503970 S2A_SUMDATA1_CUS_Reserve5_34 "客户预留数据";
CM_ SG_ 2339503970 S2A_SUMDATA1_CUS_Reserve6_34 "客户预留数据";
CM_ SG_ 2339503970 S2A_SUMDATA1_CUS_Reserve7_34 "客户预留数据";
CM_ SG_ 2339503970 S2A_SUMDATA1_CUS_Reserve8_34 "客户预留数据";
CM_ SG_ 2339503971 S2A_SUMDATA1_CUS_Reserve1_35 "客户预留数据";
CM_ SG_ 2339503971 S2A_SUMDATA1_CUS_Reserve2_35 "客户预留数据";
CM_ SG_ 2339503971 S2A_SUMDATA1_CUS_Reserve3_35 "客户预留数据";
CM_ SG_ 2339503971 S2A_SUMDATA1_CUS_Reserve4_35 "客户预留数据";
CM_ SG_ 2339503971 S2A_SUMDATA1_CUS_Reserve5_35 "客户预留数据";
CM_ SG_ 2339503971 S2A_SUMDATA1_CUS_Reserve6_35 "客户预留数据";
CM_ SG_ 2339503971 S2A_SUMDATA1_CUS_Reserve7_35 "客户预留数据";
CM_ SG_ 2339503971 S2A_SUMDATA1_CUS_Reserve8_35 "客户预留数据";
CM_ SG_ 2339503972 S2A_SUMDATA1_CUS_Reserve1_36 "客户预留数据";
CM_ SG_ 2339503972 S2A_SUMDATA1_CUS_Reserve2_36 "客户预留数据";
CM_ SG_ 2339503972 S2A_SUMDATA1_CUS_Reserve3_36 "客户预留数据";
CM_ SG_ 2339503972 S2A_SUMDATA1_CUS_Reserve4_36 "客户预留数据";
CM_ SG_ 2339503972 S2A_SUMDATA1_CUS_Reserve5_36 "客户预留数据";
CM_ SG_ 2339503972 S2A_SUMDATA1_CUS_Reserve6_36 "客户预留数据";
CM_ SG_ 2339503972 S2A_SUMDATA1_CUS_Reserve7_36 "客户预留数据";
CM_ SG_ 2339503972 S2A_SUMDATA1_CUS_Reserve8_36 "客户预留数据";
CM_ SG_ 2339503973 S2A_SUMDATA1_CUS_Reserve1_37 "客户预留数据";
CM_ SG_ 2339503973 S2A_SUMDATA1_CUS_Reserve2_37 "客户预留数据";
CM_ SG_ 2339503973 S2A_SUMDATA1_CUS_Reserve3_37 "客户预留数据";
CM_ SG_ 2339503973 S2A_SUMDATA1_CUS_Reserve4_37 "客户预留数据";
CM_ SG_ 2339503973 S2A_SUMDATA1_CUS_Reserve5_37 "客户预留数据";
CM_ SG_ 2339503973 S2A_SUMDATA1_CUS_Reserve6_37 "客户预留数据";
CM_ SG_ 2339503973 S2A_SUMDATA1_CUS_Reserve7_37 "客户预留数据";
CM_ SG_ 2339503973 S2A_SUMDATA1_CUS_Reserve8_37 "客户预留数据";
CM_ SG_ 2339503974 S2A_SUMDATA1_CUS_Reserve1_38 "客户预留数据";
CM_ SG_ 2339503974 S2A_SUMDATA1_CUS_Reserve2_38 "客户预留数据";
CM_ SG_ 2339503974 S2A_SUMDATA1_CUS_Reserve3_38 "客户预留数据";
CM_ SG_ 2339503974 S2A_SUMDATA1_CUS_Reserve4_38 "客户预留数据";
CM_ SG_ 2339503974 S2A_SUMDATA1_CUS_Reserve5_38 "客户预留数据";
CM_ SG_ 2339503974 S2A_SUMDATA1_CUS_Reserve6_38 "客户预留数据";
CM_ SG_ 2339503974 S2A_SUMDATA1_CUS_Reserve7_38 "客户预留数据";
CM_ SG_ 2339503974 S2A_SUMDATA1_CUS_Reserve8_38 "客户预留数据";
CM_ SG_ 2339503975 S2A_SUMDATA1_CUS_Reserve1_39 "客户预留数据";
CM_ SG_ 2339503975 S2A_SUMDATA1_CUS_Reserve2_39 "客户预留数据";
CM_ SG_ 2339503975 S2A_SUMDATA1_CUS_Reserve3_39 "客户预留数据";
CM_ SG_ 2339503975 S2A_SUMDATA1_CUS_Reserve4_39 "客户预留数据";
CM_ SG_ 2339503975 S2A_SUMDATA1_CUS_Reserve5_39 "客户预留数据";
CM_ SG_ 2339503975 S2A_SUMDATA1_CUS_Reserve6_39 "客户预留数据";
CM_ SG_ 2339503975 S2A_SUMDATA1_CUS_Reserve7_39 "客户预留数据";
CM_ SG_ 2339503975 S2A_SUMDATA1_CUS_Reserve8_39 "客户预留数据";
CM_ SG_ 2339503976 S2A_SUMDATA1_CUS_Reserve1_40 "客户预留数据";
CM_ SG_ 2339503976 S2A_SUMDATA1_CUS_Reserve2_40 "客户预留数据";
CM_ SG_ 2339503976 S2A_SUMDATA1_CUS_Reserve3_40 "客户预留数据";
CM_ SG_ 2339503976 S2A_SUMDATA1_CUS_Reserve4_40 "客户预留数据";
CM_ SG_ 2339503976 S2A_SUMDATA1_CUS_Reserve5_40 "客户预留数据";
CM_ SG_ 2339503976 S2A_SUMDATA1_CUS_Reserve6_40 "客户预留数据";
CM_ SG_ 2339503976 S2A_SUMDATA1_CUS_Reserve7_40 "客户预留数据";
CM_ SG_ 2339503976 S2A_SUMDATA1_CUS_Reserve8_40 "客户预留数据";
CM_ SG_ 2339503977 S2A_SUMDATA1_CUS_Reserve1_41 "客户预留数据";
CM_ SG_ 2339503977 S2A_SUMDATA1_CUS_Reserve2_41 "客户预留数据";
CM_ SG_ 2339503977 S2A_SUMDATA1_CUS_Reserve3_41 "客户预留数据";
CM_ SG_ 2339503977 S2A_SUMDATA1_CUS_Reserve4_41 "客户预留数据";
CM_ SG_ 2339503977 S2A_SUMDATA1_CUS_Reserve5_41 "客户预留数据";
CM_ SG_ 2339503977 S2A_SUMDATA1_CUS_Reserve6_41 "客户预留数据";
CM_ SG_ 2339503977 S2A_SUMDATA1_CUS_Reserve7_41 "客户预留数据";
CM_ SG_ 2339503977 S2A_SUMDATA1_CUS_Reserve8_41 "客户预留数据";
CM_ SG_ 2339503978 S2A_SUMDATA1_CUS_Reserve1_42 "客户预留数据";
CM_ SG_ 2339503978 S2A_SUMDATA1_CUS_Reserve2_42 "客户预留数据";
CM_ SG_ 2339503978 S2A_SUMDATA1_CUS_Reserve3_42 "客户预留数据";
CM_ SG_ 2339503978 S2A_SUMDATA1_CUS_Reserve4_42 "客户预留数据";
CM_ SG_ 2339503978 S2A_SUMDATA1_CUS_Reserve5_42 "客户预留数据";
CM_ SG_ 2339503978 S2A_SUMDATA1_CUS_Reserve6_42 "客户预留数据";
CM_ SG_ 2339503978 S2A_SUMDATA1_CUS_Reserve7_42 "客户预留数据";
CM_ SG_ 2339503978 S2A_SUMDATA1_CUS_Reserve8_42 "客户预留数据";
CM_ SG_ 2339503979 S2A_SUMDATA1_CUS_Reserve1_43 "客户预留数据";
CM_ SG_ 2339503979 S2A_SUMDATA1_CUS_Reserve2_43 "客户预留数据";
CM_ SG_ 2339503979 S2A_SUMDATA1_CUS_Reserve3_43 "客户预留数据";
CM_ SG_ 2339503979 S2A_SUMDATA1_CUS_Reserve4_43 "客户预留数据";
CM_ SG_ 2339503979 S2A_SUMDATA1_CUS_Reserve5_43 "客户预留数据";
CM_ SG_ 2339503979 S2A_SUMDATA1_CUS_Reserve6_43 "客户预留数据";
CM_ SG_ 2339503979 S2A_SUMDATA1_CUS_Reserve7_43 "客户预留数据";
CM_ SG_ 2339503979 S2A_SUMDATA1_CUS_Reserve8_43 "客户预留数据";
CM_ SG_ 2339503980 S2A_SUMDATA1_CUS_Reserve1_44 "客户预留数据";
CM_ SG_ 2339503980 S2A_SUMDATA1_CUS_Reserve2_44 "客户预留数据";
CM_ SG_ 2339503980 S2A_SUMDATA1_CUS_Reserve3_44 "客户预留数据";
CM_ SG_ 2339503980 S2A_SUMDATA1_CUS_Reserve4_44 "客户预留数据";
CM_ SG_ 2339503980 S2A_SUMDATA1_CUS_Reserve5_44 "客户预留数据";
CM_ SG_ 2339503980 S2A_SUMDATA1_CUS_Reserve6_44 "客户预留数据";
CM_ SG_ 2339503980 S2A_SUMDATA1_CUS_Reserve7_44 "客户预留数据";
CM_ SG_ 2339503980 S2A_SUMDATA1_CUS_Reserve8_44 "客户预留数据";
CM_ SG_ 2339503981 S2A_SUMDATA1_CUS_Reserve1_45 "客户预留数据";
CM_ SG_ 2339503981 S2A_SUMDATA1_CUS_Reserve2_45 "客户预留数据";
CM_ SG_ 2339503981 S2A_SUMDATA1_CUS_Reserve3_45 "客户预留数据";
CM_ SG_ 2339503981 S2A_SUMDATA1_CUS_Reserve4_45 "客户预留数据";
CM_ SG_ 2339503981 S2A_SUMDATA1_CUS_Reserve5_45 "客户预留数据";
CM_ SG_ 2339503981 S2A_SUMDATA1_CUS_Reserve6_45 "客户预留数据";
CM_ SG_ 2339503981 S2A_SUMDATA1_CUS_Reserve7_45 "客户预留数据";
CM_ SG_ 2339503981 S2A_SUMDATA1_CUS_Reserve8_45 "客户预留数据";
CM_ SG_ 2339503982 S2A_SUMDATA1_CUS_Reserve1_46 "客户预留数据";
CM_ SG_ 2339503982 S2A_SUMDATA1_CUS_Reserve2_46 "客户预留数据";
CM_ SG_ 2339503982 S2A_SUMDATA1_CUS_Reserve3_46 "客户预留数据";
CM_ SG_ 2339503982 S2A_SUMDATA1_CUS_Reserve4_46 "客户预留数据";
CM_ SG_ 2339503982 S2A_SUMDATA1_CUS_Reserve5_46 "客户预留数据";
CM_ SG_ 2339503982 S2A_SUMDATA1_CUS_Reserve6_46 "客户预留数据";
CM_ SG_ 2339503982 S2A_SUMDATA1_CUS_Reserve7_46 "客户预留数据";
CM_ SG_ 2339503982 S2A_SUMDATA1_CUS_Reserve8_46 "客户预留数据";
CM_ SG_ 2339503983 S2A_SUMDATA1_CUS_Reserve1_47 "客户预留数据";
CM_ SG_ 2339503983 S2A_SUMDATA1_CUS_Reserve2_47 "客户预留数据";
CM_ SG_ 2339503983 S2A_SUMDATA1_CUS_Reserve3_47 "客户预留数据";
CM_ SG_ 2339503983 S2A_SUMDATA1_CUS_Reserve4_47 "客户预留数据";
CM_ SG_ 2339503983 S2A_SUMDATA1_CUS_Reserve5_47 "客户预留数据";
CM_ SG_ 2339503983 S2A_SUMDATA1_CUS_Reserve6_47 "客户预留数据";
CM_ SG_ 2339503983 S2A_SUMDATA1_CUS_Reserve7_47 "客户预留数据";
CM_ SG_ 2339503983 S2A_SUMDATA1_CUS_Reserve8_47 "客户预留数据";
CM_ SG_ 2339503984 S2A_SUMDATA1_CUS_Reserve1_48 "客户预留数据";
CM_ SG_ 2339503984 S2A_SUMDATA1_CUS_Reserve2_48 "客户预留数据";
CM_ SG_ 2339503984 S2A_SUMDATA1_CUS_Reserve3_48 "客户预留数据";
CM_ SG_ 2339503984 S2A_SUMDATA1_CUS_Reserve4_48 "客户预留数据";
CM_ SG_ 2339503984 S2A_SUMDATA1_CUS_Reserve5_48 "客户预留数据";
CM_ SG_ 2339503984 S2A_SUMDATA1_CUS_Reserve6_48 "客户预留数据";
CM_ SG_ 2339503984 S2A_SUMDATA1_CUS_Reserve7_48 "客户预留数据";
CM_ SG_ 2339503984 S2A_SUMDATA1_CUS_Reserve8_48 "客户预留数据";
CM_ SG_ 2339503985 S2A_SUMDATA1_CUS_Reserve1_49 "客户预留数据";
CM_ SG_ 2339503985 S2A_SUMDATA1_CUS_Reserve2_49 "客户预留数据";
CM_ SG_ 2339503985 S2A_SUMDATA1_CUS_Reserve3_49 "客户预留数据";
CM_ SG_ 2339503985 S2A_SUMDATA1_CUS_Reserve4_49 "客户预留数据";
CM_ SG_ 2339503985 S2A_SUMDATA1_CUS_Reserve5_49 "客户预留数据";
CM_ SG_ 2339503985 S2A_SUMDATA1_CUS_Reserve6_49 "客户预留数据";
CM_ SG_ 2339503985 S2A_SUMDATA1_CUS_Reserve7_49 "客户预留数据";
CM_ SG_ 2339503985 S2A_SUMDATA1_CUS_Reserve8_49 "客户预留数据";
CM_ SG_ 2339503986 S2A_SUMDATA1_CUS_Reserve1_50 "客户预留数据";
CM_ SG_ 2339503986 S2A_SUMDATA1_CUS_Reserve2_50 "客户预留数据";
CM_ SG_ 2339503986 S2A_SUMDATA1_CUS_Reserve3_50 "客户预留数据";
CM_ SG_ 2339503986 S2A_SUMDATA1_CUS_Reserve4_50 "客户预留数据";
CM_ SG_ 2339503986 S2A_SUMDATA1_CUS_Reserve5_50 "客户预留数据";
CM_ SG_ 2339503986 S2A_SUMDATA1_CUS_Reserve6_50 "客户预留数据";
CM_ SG_ 2339503986 S2A_SUMDATA1_CUS_Reserve7_50 "客户预留数据";
CM_ SG_ 2339503986 S2A_SUMDATA1_CUS_Reserve8_50 "客户预留数据";
CM_ SG_ 2339503987 S2A_SUMDATA1_CUS_Reserve1_51 "客户预留数据";
CM_ SG_ 2339503987 S2A_SUMDATA1_CUS_Reserve2_51 "客户预留数据";
CM_ SG_ 2339503987 S2A_SUMDATA1_CUS_Reserve3_51 "客户预留数据";
CM_ SG_ 2339503987 S2A_SUMDATA1_CUS_Reserve4_51 "客户预留数据";
CM_ SG_ 2339503987 S2A_SUMDATA1_CUS_Reserve5_51 "客户预留数据";
CM_ SG_ 2339503987 S2A_SUMDATA1_CUS_Reserve6_51 "客户预留数据";
CM_ SG_ 2339503987 S2A_SUMDATA1_CUS_Reserve7_51 "客户预留数据";
CM_ SG_ 2339503987 S2A_SUMDATA1_CUS_Reserve8_51 "客户预留数据";
CM_ SG_ 2339503988 S2A_SUMDATA1_CUS_Reserve1_52 "客户预留数据";
CM_ SG_ 2339503988 S2A_SUMDATA1_CUS_Reserve2_52 "客户预留数据";
CM_ SG_ 2339503988 S2A_SUMDATA1_CUS_Reserve3_52 "客户预留数据";
CM_ SG_ 2339503988 S2A_SUMDATA1_CUS_Reserve4_52 "客户预留数据";
CM_ SG_ 2339503988 S2A_SUMDATA1_CUS_Reserve5_52 "客户预留数据";
CM_ SG_ 2339503988 S2A_SUMDATA1_CUS_Reserve6_52 "客户预留数据";
CM_ SG_ 2339503988 S2A_SUMDATA1_CUS_Reserve7_52 "客户预留数据";
CM_ SG_ 2339503988 S2A_SUMDATA1_CUS_Reserve8_52 "客户预留数据";
CM_ SG_ 2339503989 S2A_SUMDATA1_CUS_Reserve1_53 "客户预留数据";
CM_ SG_ 2339503989 S2A_SUMDATA1_CUS_Reserve2_53 "客户预留数据";
CM_ SG_ 2339503989 S2A_SUMDATA1_CUS_Reserve3_53 "客户预留数据";
CM_ SG_ 2339503989 S2A_SUMDATA1_CUS_Reserve4_53 "客户预留数据";
CM_ SG_ 2339503989 S2A_SUMDATA1_CUS_Reserve5_53 "客户预留数据";
CM_ SG_ 2339503989 S2A_SUMDATA1_CUS_Reserve6_53 "客户预留数据";
CM_ SG_ 2339503989 S2A_SUMDATA1_CUS_Reserve7_53 "客户预留数据";
CM_ SG_ 2339503989 S2A_SUMDATA1_CUS_Reserve8_53 "客户预留数据";
CM_ SG_ 2339503990 S2A_SUMDATA1_CUS_Reserve1_54 "客户预留数据";
CM_ SG_ 2339503990 S2A_SUMDATA1_CUS_Reserve2_54 "客户预留数据";
CM_ SG_ 2339503990 S2A_SUMDATA1_CUS_Reserve3_54 "客户预留数据";
CM_ SG_ 2339503990 S2A_SUMDATA1_CUS_Reserve4_54 "客户预留数据";
CM_ SG_ 2339503990 S2A_SUMDATA1_CUS_Reserve5_54 "客户预留数据";
CM_ SG_ 2339503990 S2A_SUMDATA1_CUS_Reserve6_54 "客户预留数据";
CM_ SG_ 2339503990 S2A_SUMDATA1_CUS_Reserve7_54 "客户预留数据";
CM_ SG_ 2339503990 S2A_SUMDATA1_CUS_Reserve8_54 "客户预留数据";
CM_ SG_ 2339503991 S2A_SUMDATA1_CUS_Reserve1_55 "客户预留数据";
CM_ SG_ 2339503991 S2A_SUMDATA1_CUS_Reserve2_55 "客户预留数据";
CM_ SG_ 2339503991 S2A_SUMDATA1_CUS_Reserve3_55 "客户预留数据";
CM_ SG_ 2339503991 S2A_SUMDATA1_CUS_Reserve4_55 "客户预留数据";
CM_ SG_ 2339503991 S2A_SUMDATA1_CUS_Reserve5_55 "客户预留数据";
CM_ SG_ 2339503991 S2A_SUMDATA1_CUS_Reserve6_55 "客户预留数据";
CM_ SG_ 2339503991 S2A_SUMDATA1_CUS_Reserve7_55 "客户预留数据";
CM_ SG_ 2339503991 S2A_SUMDATA1_CUS_Reserve8_55 "客户预留数据";
CM_ SG_ 2339503992 S2A_SUMDATA1_CUS_Reserve1_56 "客户预留数据";
CM_ SG_ 2339503992 S2A_SUMDATA1_CUS_Reserve2_56 "客户预留数据";
CM_ SG_ 2339503992 S2A_SUMDATA1_CUS_Reserve3_56 "客户预留数据";
CM_ SG_ 2339503992 S2A_SUMDATA1_CUS_Reserve4_56 "客户预留数据";
CM_ SG_ 2339503992 S2A_SUMDATA1_CUS_Reserve5_56 "客户预留数据";
CM_ SG_ 2339503992 S2A_SUMDATA1_CUS_Reserve6_56 "客户预留数据";
CM_ SG_ 2339503992 S2A_SUMDATA1_CUS_Reserve7_56 "客户预留数据";
CM_ SG_ 2339503992 S2A_SUMDATA1_CUS_Reserve8_56 "客户预留数据";
CM_ SG_ 2339503993 S2A_SUMDATA1_CUS_Reserve1_57 "客户预留数据";
CM_ SG_ 2339503993 S2A_SUMDATA1_CUS_Reserve2_57 "客户预留数据";
CM_ SG_ 2339503993 S2A_SUMDATA1_CUS_Reserve3_57 "客户预留数据";
CM_ SG_ 2339503993 S2A_SUMDATA1_CUS_Reserve4_57 "客户预留数据";
CM_ SG_ 2339503993 S2A_SUMDATA1_CUS_Reserve5_57 "客户预留数据";
CM_ SG_ 2339503993 S2A_SUMDATA1_CUS_Reserve6_57 "客户预留数据";
CM_ SG_ 2339503993 S2A_SUMDATA1_CUS_Reserve7_57 "客户预留数据";
CM_ SG_ 2339503993 S2A_SUMDATA1_CUS_Reserve8_57 "客户预留数据";
CM_ SG_ 2339503994 S2A_SUMDATA1_CUS_Reserve1_58 "客户预留数据";
CM_ SG_ 2339503994 S2A_SUMDATA1_CUS_Reserve2_58 "客户预留数据";
CM_ SG_ 2339503994 S2A_SUMDATA1_CUS_Reserve3_58 "客户预留数据";
CM_ SG_ 2339503994 S2A_SUMDATA1_CUS_Reserve4_58 "客户预留数据";
CM_ SG_ 2339503994 S2A_SUMDATA1_CUS_Reserve5_58 "客户预留数据";
CM_ SG_ 2339503994 S2A_SUMDATA1_CUS_Reserve6_58 "客户预留数据";
CM_ SG_ 2339503994 S2A_SUMDATA1_CUS_Reserve7_58 "客户预留数据";
CM_ SG_ 2339503994 S2A_SUMDATA1_CUS_Reserve8_58 "客户预留数据";
CM_ SG_ 2339503995 S2A_SUMDATA1_CUS_Reserve1_59 "客户预留数据";
CM_ SG_ 2339503995 S2A_SUMDATA1_CUS_Reserve2_59 "客户预留数据";
CM_ SG_ 2339503995 S2A_SUMDATA1_CUS_Reserve3_59 "客户预留数据";
CM_ SG_ 2339503995 S2A_SUMDATA1_CUS_Reserve4_59 "客户预留数据";
CM_ SG_ 2339503995 S2A_SUMDATA1_CUS_Reserve5_59 "客户预留数据";
CM_ SG_ 2339503995 S2A_SUMDATA1_CUS_Reserve6_59 "客户预留数据";
CM_ SG_ 2339503995 S2A_SUMDATA1_CUS_Reserve7_59 "客户预留数据";
CM_ SG_ 2339503995 S2A_SUMDATA1_CUS_Reserve8_59 "客户预留数据";
CM_ SG_ 2339503996 S2A_SUMDATA1_CUS_Reserve1_60 "客户预留数据";
CM_ SG_ 2339503996 S2A_SUMDATA1_CUS_Reserve2_60 "客户预留数据";
CM_ SG_ 2339503996 S2A_SUMDATA1_CUS_Reserve3_60 "客户预留数据";
CM_ SG_ 2339503996 S2A_SUMDATA1_CUS_Reserve4_60 "客户预留数据";
CM_ SG_ 2339503996 S2A_SUMDATA1_CUS_Reserve5_60 "客户预留数据";
CM_ SG_ 2339503996 S2A_SUMDATA1_CUS_Reserve6_60 "客户预留数据";
CM_ SG_ 2339503996 S2A_SUMDATA1_CUS_Reserve7_60 "客户预留数据";
CM_ SG_ 2339503996 S2A_SUMDATA1_CUS_Reserve8_60 "客户预留数据";
CM_ SG_ 2339503997 S2A_SUMDATA1_CUS_Reserve1_61 "客户预留数据";
CM_ SG_ 2339503997 S2A_SUMDATA1_CUS_Reserve2_61 "客户预留数据";
CM_ SG_ 2339503997 S2A_SUMDATA1_CUS_Reserve3_61 "客户预留数据";
CM_ SG_ 2339503997 S2A_SUMDATA1_CUS_Reserve4_61 "客户预留数据";
CM_ SG_ 2339503997 S2A_SUMDATA1_CUS_Reserve5_61 "客户预留数据";
CM_ SG_ 2339503997 S2A_SUMDATA1_CUS_Reserve6_61 "客户预留数据";
CM_ SG_ 2339503997 S2A_SUMDATA1_CUS_Reserve7_61 "客户预留数据";
CM_ SG_ 2339503997 S2A_SUMDATA1_CUS_Reserve8_61 "客户预留数据";
CM_ SG_ 2339503998 S2A_SUMDATA1_CUS_Reserve1_62 "客户预留数据";
CM_ SG_ 2339503998 S2A_SUMDATA1_CUS_Reserve2_62 "客户预留数据";
CM_ SG_ 2339503998 S2A_SUMDATA1_CUS_Reserve3_62 "客户预留数据";
CM_ SG_ 2339503998 S2A_SUMDATA1_CUS_Reserve4_62 "客户预留数据";
CM_ SG_ 2339503998 S2A_SUMDATA1_CUS_Reserve5_62 "客户预留数据";
CM_ SG_ 2339503998 S2A_SUMDATA1_CUS_Reserve6_62 "客户预留数据";
CM_ SG_ 2339503998 S2A_SUMDATA1_CUS_Reserve7_62 "客户预留数据";
CM_ SG_ 2339503998 S2A_SUMDATA1_CUS_Reserve8_62 "客户预留数据";
CM_ SG_ 2339503999 S2A_SUMDATA1_CUS_Reserve1_63 "客户预留数据";
CM_ SG_ 2339503999 S2A_SUMDATA1_CUS_Reserve2_63 "客户预留数据";
CM_ SG_ 2339503999 S2A_SUMDATA1_CUS_Reserve3_63 "客户预留数据";
CM_ SG_ 2339503999 S2A_SUMDATA1_CUS_Reserve4_63 "客户预留数据";
CM_ SG_ 2339503999 S2A_SUMDATA1_CUS_Reserve5_63 "客户预留数据";
CM_ SG_ 2339503999 S2A_SUMDATA1_CUS_Reserve6_63 "客户预留数据";
CM_ SG_ 2339503999 S2A_SUMDATA1_CUS_Reserve7_63 "客户预留数据";
CM_ SG_ 2339503999 S2A_SUMDATA1_CUS_Reserve8_63 "客户预留数据";
CM_ SG_ 2339569473 S2A_SUMDATA2_CUS_Reserve1_01 "客户预留数据";
CM_ SG_ 2339569473 S2A_SUMDATA2_CUS_Reserve2_01 "客户预留数据";
CM_ SG_ 2339569473 S2A_SUMDATA2_CUS_Reserve3_01 "客户预留数据";
CM_ SG_ 2339569473 S2A_SUMDATA2_CUS_Reserve4_01 "客户预留数据";
CM_ SG_ 2339569473 S2A_SUMDATA2_CUS_Reserve5_01 "客户预留数据";
CM_ SG_ 2339569473 S2A_SUMDATA2_CUS_Reserve6_01 "客户预留数据";
CM_ SG_ 2339569473 S2A_SUMDATA2_CUS_Reserve7_01 "客户预留数据";
CM_ SG_ 2339569473 S2A_SUMDATA2_CUS_Reserve8_01 "客户预留数据";
CM_ SG_ 2339569474 S2A_SUMDATA2_CUS_Reserve1_02 "客户预留数据";
CM_ SG_ 2339569474 S2A_SUMDATA2_CUS_Reserve2_02 "客户预留数据";
CM_ SG_ 2339569474 S2A_SUMDATA2_CUS_Reserve3_02 "客户预留数据";
CM_ SG_ 2339569474 S2A_SUMDATA2_CUS_Reserve4_02 "客户预留数据";
CM_ SG_ 2339569474 S2A_SUMDATA2_CUS_Reserve5_02 "客户预留数据";
CM_ SG_ 2339569474 S2A_SUMDATA2_CUS_Reserve6_02 "客户预留数据";
CM_ SG_ 2339569474 S2A_SUMDATA2_CUS_Reserve7_02 "客户预留数据";
CM_ SG_ 2339569474 S2A_SUMDATA2_CUS_Reserve8_02 "客户预留数据";
CM_ SG_ 2339569475 S2A_SUMDATA2_CUS_Reserve1_03 "客户预留数据";
CM_ SG_ 2339569475 S2A_SUMDATA2_CUS_Reserve2_03 "客户预留数据";
CM_ SG_ 2339569475 S2A_SUMDATA2_CUS_Reserve3_03 "客户预留数据";
CM_ SG_ 2339569475 S2A_SUMDATA2_CUS_Reserve4_03 "客户预留数据";
CM_ SG_ 2339569475 S2A_SUMDATA2_CUS_Reserve5_03 "客户预留数据";
CM_ SG_ 2339569475 S2A_SUMDATA2_CUS_Reserve6_03 "客户预留数据";
CM_ SG_ 2339569475 S2A_SUMDATA2_CUS_Reserve7_03 "客户预留数据";
CM_ SG_ 2339569475 S2A_SUMDATA2_CUS_Reserve8_03 "客户预留数据";
CM_ SG_ 2339569476 S2A_SUMDATA2_CUS_Reserve1_04 "客户预留数据";
CM_ SG_ 2339569476 S2A_SUMDATA2_CUS_Reserve2_04 "客户预留数据";
CM_ SG_ 2339569476 S2A_SUMDATA2_CUS_Reserve3_04 "客户预留数据";
CM_ SG_ 2339569476 S2A_SUMDATA2_CUS_Reserve4_04 "客户预留数据";
CM_ SG_ 2339569476 S2A_SUMDATA2_CUS_Reserve5_04 "客户预留数据";
CM_ SG_ 2339569476 S2A_SUMDATA2_CUS_Reserve6_04 "客户预留数据";
CM_ SG_ 2339569476 S2A_SUMDATA2_CUS_Reserve7_04 "客户预留数据";
CM_ SG_ 2339569476 S2A_SUMDATA2_CUS_Reserve8_04 "客户预留数据";
CM_ SG_ 2339569477 S2A_SUMDATA2_CUS_Reserve1_05 "客户预留数据";
CM_ SG_ 2339569477 S2A_SUMDATA2_CUS_Reserve2_05 "客户预留数据";
CM_ SG_ 2339569477 S2A_SUMDATA2_CUS_Reserve3_05 "客户预留数据";
CM_ SG_ 2339569477 S2A_SUMDATA2_CUS_Reserve4_05 "客户预留数据";
CM_ SG_ 2339569477 S2A_SUMDATA2_CUS_Reserve5_05 "客户预留数据";
CM_ SG_ 2339569477 S2A_SUMDATA2_CUS_Reserve6_05 "客户预留数据";
CM_ SG_ 2339569477 S2A_SUMDATA2_CUS_Reserve7_05 "客户预留数据";
CM_ SG_ 2339569477 S2A_SUMDATA2_CUS_Reserve8_05 "客户预留数据";
CM_ SG_ 2339569478 S2A_SUMDATA2_CUS_Reserve1_06 "客户预留数据";
CM_ SG_ 2339569478 S2A_SUMDATA2_CUS_Reserve2_06 "客户预留数据";
CM_ SG_ 2339569478 S2A_SUMDATA2_CUS_Reserve3_06 "客户预留数据";
CM_ SG_ 2339569478 S2A_SUMDATA2_CUS_Reserve4_06 "客户预留数据";
CM_ SG_ 2339569478 S2A_SUMDATA2_CUS_Reserve5_06 "客户预留数据";
CM_ SG_ 2339569478 S2A_SUMDATA2_CUS_Reserve6_06 "客户预留数据";
CM_ SG_ 2339569478 S2A_SUMDATA2_CUS_Reserve7_06 "客户预留数据";
CM_ SG_ 2339569478 S2A_SUMDATA2_CUS_Reserve8_06 "客户预留数据";
CM_ SG_ 2339569479 S2A_SUMDATA2_CUS_Reserve1_07 "客户预留数据";
CM_ SG_ 2339569479 S2A_SUMDATA2_CUS_Reserve2_07 "客户预留数据";
CM_ SG_ 2339569479 S2A_SUMDATA2_CUS_Reserve3_07 "客户预留数据";
CM_ SG_ 2339569479 S2A_SUMDATA2_CUS_Reserve4_07 "客户预留数据";
CM_ SG_ 2339569479 S2A_SUMDATA2_CUS_Reserve5_07 "客户预留数据";
CM_ SG_ 2339569479 S2A_SUMDATA2_CUS_Reserve6_07 "客户预留数据";
CM_ SG_ 2339569479 S2A_SUMDATA2_CUS_Reserve7_07 "客户预留数据";
CM_ SG_ 2339569479 S2A_SUMDATA2_CUS_Reserve8_07 "客户预留数据";
CM_ SG_ 2339569480 S2A_SUMDATA2_CUS_Reserve1_08 "客户预留数据";
CM_ SG_ 2339569480 S2A_SUMDATA2_CUS_Reserve2_08 "客户预留数据";
CM_ SG_ 2339569480 S2A_SUMDATA2_CUS_Reserve3_08 "客户预留数据";
CM_ SG_ 2339569480 S2A_SUMDATA2_CUS_Reserve4_08 "客户预留数据";
CM_ SG_ 2339569480 S2A_SUMDATA2_CUS_Reserve5_08 "客户预留数据";
CM_ SG_ 2339569480 S2A_SUMDATA2_CUS_Reserve6_08 "客户预留数据";
CM_ SG_ 2339569480 S2A_SUMDATA2_CUS_Reserve7_08 "客户预留数据";
CM_ SG_ 2339569480 S2A_SUMDATA2_CUS_Reserve8_08 "客户预留数据";
CM_ SG_ 2339569481 S2A_SUMDATA2_CUS_Reserve1_09 "客户预留数据";
CM_ SG_ 2339569481 S2A_SUMDATA2_CUS_Reserve2_09 "客户预留数据";
CM_ SG_ 2339569481 S2A_SUMDATA2_CUS_Reserve3_09 "客户预留数据";
CM_ SG_ 2339569481 S2A_SUMDATA2_CUS_Reserve4_09 "客户预留数据";
CM_ SG_ 2339569481 S2A_SUMDATA2_CUS_Reserve5_09 "客户预留数据";
CM_ SG_ 2339569481 S2A_SUMDATA2_CUS_Reserve6_09 "客户预留数据";
CM_ SG_ 2339569481 S2A_SUMDATA2_CUS_Reserve7_09 "客户预留数据";
CM_ SG_ 2339569481 S2A_SUMDATA2_CUS_Reserve8_09 "客户预留数据";
CM_ SG_ 2339569482 S2A_SUMDATA2_CUS_Reserve1_10 "客户预留数据";
CM_ SG_ 2339569482 S2A_SUMDATA2_CUS_Reserve2_10 "客户预留数据";
CM_ SG_ 2339569482 S2A_SUMDATA2_CUS_Reserve3_10 "客户预留数据";
CM_ SG_ 2339569482 S2A_SUMDATA2_CUS_Reserve4_10 "客户预留数据";
CM_ SG_ 2339569482 S2A_SUMDATA2_CUS_Reserve5_10 "客户预留数据";
CM_ SG_ 2339569482 S2A_SUMDATA2_CUS_Reserve6_10 "客户预留数据";
CM_ SG_ 2339569482 S2A_SUMDATA2_CUS_Reserve7_10 "客户预留数据";
CM_ SG_ 2339569482 S2A_SUMDATA2_CUS_Reserve8_10 "客户预留数据";
CM_ SG_ 2339569483 S2A_SUMDATA2_CUS_Reserve1_11 "客户预留数据";
CM_ SG_ 2339569483 S2A_SUMDATA2_CUS_Reserve2_11 "客户预留数据";
CM_ SG_ 2339569483 S2A_SUMDATA2_CUS_Reserve3_11 "客户预留数据";
CM_ SG_ 2339569483 S2A_SUMDATA2_CUS_Reserve4_11 "客户预留数据";
CM_ SG_ 2339569483 S2A_SUMDATA2_CUS_Reserve5_11 "客户预留数据";
CM_ SG_ 2339569483 S2A_SUMDATA2_CUS_Reserve6_11 "客户预留数据";
CM_ SG_ 2339569483 S2A_SUMDATA2_CUS_Reserve7_11 "客户预留数据";
CM_ SG_ 2339569483 S2A_SUMDATA2_CUS_Reserve8_11 "客户预留数据";
CM_ SG_ 2339569484 S2A_SUMDATA2_CUS_Reserve1_12 "客户预留数据";
CM_ SG_ 2339569484 S2A_SUMDATA2_CUS_Reserve2_12 "客户预留数据";
CM_ SG_ 2339569484 S2A_SUMDATA2_CUS_Reserve3_12 "客户预留数据";
CM_ SG_ 2339569484 S2A_SUMDATA2_CUS_Reserve4_12 "客户预留数据";
CM_ SG_ 2339569484 S2A_SUMDATA2_CUS_Reserve5_12 "客户预留数据";
CM_ SG_ 2339569484 S2A_SUMDATA2_CUS_Reserve6_12 "客户预留数据";
CM_ SG_ 2339569484 S2A_SUMDATA2_CUS_Reserve7_12 "客户预留数据";
CM_ SG_ 2339569484 S2A_SUMDATA2_CUS_Reserve8_12 "客户预留数据";
CM_ SG_ 2339569485 S2A_SUMDATA2_CUS_Reserve1_13 "客户预留数据";
CM_ SG_ 2339569485 S2A_SUMDATA2_CUS_Reserve2_13 "客户预留数据";
CM_ SG_ 2339569485 S2A_SUMDATA2_CUS_Reserve3_13 "客户预留数据";
CM_ SG_ 2339569485 S2A_SUMDATA2_CUS_Reserve4_13 "客户预留数据";
CM_ SG_ 2339569485 S2A_SUMDATA2_CUS_Reserve5_13 "客户预留数据";
CM_ SG_ 2339569485 S2A_SUMDATA2_CUS_Reserve6_13 "客户预留数据";
CM_ SG_ 2339569485 S2A_SUMDATA2_CUS_Reserve7_13 "客户预留数据";
CM_ SG_ 2339569485 S2A_SUMDATA2_CUS_Reserve8_13 "客户预留数据";
CM_ SG_ 2339569486 S2A_SUMDATA2_CUS_Reserve1_14 "客户预留数据";
CM_ SG_ 2339569486 S2A_SUMDATA2_CUS_Reserve2_14 "客户预留数据";
CM_ SG_ 2339569486 S2A_SUMDATA2_CUS_Reserve3_14 "客户预留数据";
CM_ SG_ 2339569486 S2A_SUMDATA2_CUS_Reserve4_14 "客户预留数据";
CM_ SG_ 2339569486 S2A_SUMDATA2_CUS_Reserve5_14 "客户预留数据";
CM_ SG_ 2339569486 S2A_SUMDATA2_CUS_Reserve6_14 "客户预留数据";
CM_ SG_ 2339569486 S2A_SUMDATA2_CUS_Reserve7_14 "客户预留数据";
CM_ SG_ 2339569486 S2A_SUMDATA2_CUS_Reserve8_14 "客户预留数据";
CM_ SG_ 2339569487 S2A_SUMDATA2_CUS_Reserve1_15 "客户预留数据";
CM_ SG_ 2339569487 S2A_SUMDATA2_CUS_Reserve2_15 "客户预留数据";
CM_ SG_ 2339569487 S2A_SUMDATA2_CUS_Reserve3_15 "客户预留数据";
CM_ SG_ 2339569487 S2A_SUMDATA2_CUS_Reserve4_15 "客户预留数据";
CM_ SG_ 2339569487 S2A_SUMDATA2_CUS_Reserve5_15 "客户预留数据";
CM_ SG_ 2339569487 S2A_SUMDATA2_CUS_Reserve6_15 "客户预留数据";
CM_ SG_ 2339569487 S2A_SUMDATA2_CUS_Reserve7_15 "客户预留数据";
CM_ SG_ 2339569487 S2A_SUMDATA2_CUS_Reserve8_15 "客户预留数据";
CM_ SG_ 2339569488 S2A_SUMDATA2_CUS_Reserve1_16 "客户预留数据";
CM_ SG_ 2339569488 S2A_SUMDATA2_CUS_Reserve2_16 "客户预留数据";
CM_ SG_ 2339569488 S2A_SUMDATA2_CUS_Reserve3_16 "客户预留数据";
CM_ SG_ 2339569488 S2A_SUMDATA2_CUS_Reserve4_16 "客户预留数据";
CM_ SG_ 2339569488 S2A_SUMDATA2_CUS_Reserve5_16 "客户预留数据";
CM_ SG_ 2339569488 S2A_SUMDATA2_CUS_Reserve6_16 "客户预留数据";
CM_ SG_ 2339569488 S2A_SUMDATA2_CUS_Reserve7_16 "客户预留数据";
CM_ SG_ 2339569488 S2A_SUMDATA2_CUS_Reserve8_16 "客户预留数据";
CM_ SG_ 2339569489 S2A_SUMDATA2_CUS_Reserve1_17 "客户预留数据";
CM_ SG_ 2339569489 S2A_SUMDATA2_CUS_Reserve2_17 "客户预留数据";
CM_ SG_ 2339569489 S2A_SUMDATA2_CUS_Reserve3_17 "客户预留数据";
CM_ SG_ 2339569489 S2A_SUMDATA2_CUS_Reserve4_17 "客户预留数据";
CM_ SG_ 2339569489 S2A_SUMDATA2_CUS_Reserve5_17 "客户预留数据";
CM_ SG_ 2339569489 S2A_SUMDATA2_CUS_Reserve6_17 "客户预留数据";
CM_ SG_ 2339569489 S2A_SUMDATA2_CUS_Reserve7_17 "客户预留数据";
CM_ SG_ 2339569489 S2A_SUMDATA2_CUS_Reserve8_17 "客户预留数据";
CM_ SG_ 2339569490 S2A_SUMDATA2_CUS_Reserve1_18 "客户预留数据";
CM_ SG_ 2339569490 S2A_SUMDATA2_CUS_Reserve2_18 "客户预留数据";
CM_ SG_ 2339569490 S2A_SUMDATA2_CUS_Reserve3_18 "客户预留数据";
CM_ SG_ 2339569490 S2A_SUMDATA2_CUS_Reserve4_18 "客户预留数据";
CM_ SG_ 2339569490 S2A_SUMDATA2_CUS_Reserve5_18 "客户预留数据";
CM_ SG_ 2339569490 S2A_SUMDATA2_CUS_Reserve6_18 "客户预留数据";
CM_ SG_ 2339569490 S2A_SUMDATA2_CUS_Reserve7_18 "客户预留数据";
CM_ SG_ 2339569490 S2A_SUMDATA2_CUS_Reserve8_18 "客户预留数据";
CM_ SG_ 2339569491 S2A_SUMDATA2_CUS_Reserve1_19 "客户预留数据";
CM_ SG_ 2339569491 S2A_SUMDATA2_CUS_Reserve2_19 "客户预留数据";
CM_ SG_ 2339569491 S2A_SUMDATA2_CUS_Reserve3_19 "客户预留数据";
CM_ SG_ 2339569491 S2A_SUMDATA2_CUS_Reserve4_19 "客户预留数据";
CM_ SG_ 2339569491 S2A_SUMDATA2_CUS_Reserve5_19 "客户预留数据";
CM_ SG_ 2339569491 S2A_SUMDATA2_CUS_Reserve6_19 "客户预留数据";
CM_ SG_ 2339569491 S2A_SUMDATA2_CUS_Reserve7_19 "客户预留数据";
CM_ SG_ 2339569491 S2A_SUMDATA2_CUS_Reserve8_19 "客户预留数据";
CM_ SG_ 2339569492 S2A_SUMDATA2_CUS_Reserve1_20 "客户预留数据";
CM_ SG_ 2339569492 S2A_SUMDATA2_CUS_Reserve2_20 "客户预留数据";
CM_ SG_ 2339569492 S2A_SUMDATA2_CUS_Reserve3_20 "客户预留数据";
CM_ SG_ 2339569492 S2A_SUMDATA2_CUS_Reserve4_20 "客户预留数据";
CM_ SG_ 2339569492 S2A_SUMDATA2_CUS_Reserve5_20 "客户预留数据";
CM_ SG_ 2339569492 S2A_SUMDATA2_CUS_Reserve6_20 "客户预留数据";
CM_ SG_ 2339569492 S2A_SUMDATA2_CUS_Reserve7_20 "客户预留数据";
CM_ SG_ 2339569492 S2A_SUMDATA2_CUS_Reserve8_20 "客户预留数据";
CM_ SG_ 2339569493 S2A_SUMDATA2_CUS_Reserve1_21 "客户预留数据";
CM_ SG_ 2339569493 S2A_SUMDATA2_CUS_Reserve2_21 "客户预留数据";
CM_ SG_ 2339569493 S2A_SUMDATA2_CUS_Reserve3_21 "客户预留数据";
CM_ SG_ 2339569493 S2A_SUMDATA2_CUS_Reserve4_21 "客户预留数据";
CM_ SG_ 2339569493 S2A_SUMDATA2_CUS_Reserve5_21 "客户预留数据";
CM_ SG_ 2339569493 S2A_SUMDATA2_CUS_Reserve6_21 "客户预留数据";
CM_ SG_ 2339569493 S2A_SUMDATA2_CUS_Reserve7_21 "客户预留数据";
CM_ SG_ 2339569493 S2A_SUMDATA2_CUS_Reserve8_21 "客户预留数据";
CM_ SG_ 2339569494 S2A_SUMDATA2_CUS_Reserve1_22 "客户预留数据";
CM_ SG_ 2339569494 S2A_SUMDATA2_CUS_Reserve2_22 "客户预留数据";
CM_ SG_ 2339569494 S2A_SUMDATA2_CUS_Reserve3_22 "客户预留数据";
CM_ SG_ 2339569494 S2A_SUMDATA2_CUS_Reserve4_22 "客户预留数据";
CM_ SG_ 2339569494 S2A_SUMDATA2_CUS_Reserve5_22 "客户预留数据";
CM_ SG_ 2339569494 S2A_SUMDATA2_CUS_Reserve6_22 "客户预留数据";
CM_ SG_ 2339569494 S2A_SUMDATA2_CUS_Reserve7_22 "客户预留数据";
CM_ SG_ 2339569494 S2A_SUMDATA2_CUS_Reserve8_22 "客户预留数据";
CM_ SG_ 2339569495 S2A_SUMDATA2_CUS_Reserve1_23 "客户预留数据";
CM_ SG_ 2339569495 S2A_SUMDATA2_CUS_Reserve2_23 "客户预留数据";
CM_ SG_ 2339569495 S2A_SUMDATA2_CUS_Reserve3_23 "客户预留数据";
CM_ SG_ 2339569495 S2A_SUMDATA2_CUS_Reserve4_23 "客户预留数据";
CM_ SG_ 2339569495 S2A_SUMDATA2_CUS_Reserve5_23 "客户预留数据";
CM_ SG_ 2339569495 S2A_SUMDATA2_CUS_Reserve6_23 "客户预留数据";
CM_ SG_ 2339569495 S2A_SUMDATA2_CUS_Reserve7_23 "客户预留数据";
CM_ SG_ 2339569495 S2A_SUMDATA2_CUS_Reserve8_23 "客户预留数据";
CM_ SG_ 2339569496 S2A_SUMDATA2_CUS_Reserve1_24 "客户预留数据";
CM_ SG_ 2339569496 S2A_SUMDATA2_CUS_Reserve2_24 "客户预留数据";
CM_ SG_ 2339569496 S2A_SUMDATA2_CUS_Reserve3_24 "客户预留数据";
CM_ SG_ 2339569496 S2A_SUMDATA2_CUS_Reserve4_24 "客户预留数据";
CM_ SG_ 2339569496 S2A_SUMDATA2_CUS_Reserve5_24 "客户预留数据";
CM_ SG_ 2339569496 S2A_SUMDATA2_CUS_Reserve6_24 "客户预留数据";
CM_ SG_ 2339569496 S2A_SUMDATA2_CUS_Reserve7_24 "客户预留数据";
CM_ SG_ 2339569496 S2A_SUMDATA2_CUS_Reserve8_24 "客户预留数据";
CM_ SG_ 2339569497 S2A_SUMDATA2_CUS_Reserve1_25 "客户预留数据";
CM_ SG_ 2339569497 S2A_SUMDATA2_CUS_Reserve2_25 "客户预留数据";
CM_ SG_ 2339569497 S2A_SUMDATA2_CUS_Reserve3_25 "客户预留数据";
CM_ SG_ 2339569497 S2A_SUMDATA2_CUS_Reserve4_25 "客户预留数据";
CM_ SG_ 2339569497 S2A_SUMDATA2_CUS_Reserve5_25 "客户预留数据";
CM_ SG_ 2339569497 S2A_SUMDATA2_CUS_Reserve6_25 "客户预留数据";
CM_ SG_ 2339569497 S2A_SUMDATA2_CUS_Reserve7_25 "客户预留数据";
CM_ SG_ 2339569497 S2A_SUMDATA2_CUS_Reserve8_25 "客户预留数据";
CM_ SG_ 2339569498 S2A_SUMDATA2_CUS_Reserve1_26 "客户预留数据";
CM_ SG_ 2339569498 S2A_SUMDATA2_CUS_Reserve2_26 "客户预留数据";
CM_ SG_ 2339569498 S2A_SUMDATA2_CUS_Reserve3_26 "客户预留数据";
CM_ SG_ 2339569498 S2A_SUMDATA2_CUS_Reserve4_26 "客户预留数据";
CM_ SG_ 2339569498 S2A_SUMDATA2_CUS_Reserve5_26 "客户预留数据";
CM_ SG_ 2339569498 S2A_SUMDATA2_CUS_Reserve6_26 "客户预留数据";
CM_ SG_ 2339569498 S2A_SUMDATA2_CUS_Reserve7_26 "客户预留数据";
CM_ SG_ 2339569498 S2A_SUMDATA2_CUS_Reserve8_26 "客户预留数据";
CM_ SG_ 2339569499 S2A_SUMDATA2_CUS_Reserve1_27 "客户预留数据";
CM_ SG_ 2339569499 S2A_SUMDATA2_CUS_Reserve2_27 "客户预留数据";
CM_ SG_ 2339569499 S2A_SUMDATA2_CUS_Reserve3_27 "客户预留数据";
CM_ SG_ 2339569499 S2A_SUMDATA2_CUS_Reserve4_27 "客户预留数据";
CM_ SG_ 2339569499 S2A_SUMDATA2_CUS_Reserve5_27 "客户预留数据";
CM_ SG_ 2339569499 S2A_SUMDATA2_CUS_Reserve6_27 "客户预留数据";
CM_ SG_ 2339569499 S2A_SUMDATA2_CUS_Reserve7_27 "客户预留数据";
CM_ SG_ 2339569499 S2A_SUMDATA2_CUS_Reserve8_27 "客户预留数据";
CM_ SG_ 2339569500 S2A_SUMDATA2_CUS_Reserve1_28 "客户预留数据";
CM_ SG_ 2339569500 S2A_SUMDATA2_CUS_Reserve2_28 "客户预留数据";
CM_ SG_ 2339569500 S2A_SUMDATA2_CUS_Reserve3_28 "客户预留数据";
CM_ SG_ 2339569500 S2A_SUMDATA2_CUS_Reserve4_28 "客户预留数据";
CM_ SG_ 2339569500 S2A_SUMDATA2_CUS_Reserve5_28 "客户预留数据";
CM_ SG_ 2339569500 S2A_SUMDATA2_CUS_Reserve6_28 "客户预留数据";
CM_ SG_ 2339569500 S2A_SUMDATA2_CUS_Reserve7_28 "客户预留数据";
CM_ SG_ 2339569500 S2A_SUMDATA2_CUS_Reserve8_28 "客户预留数据";
CM_ SG_ 2339569501 S2A_SUMDATA2_CUS_Reserve1_29 "客户预留数据";
CM_ SG_ 2339569501 S2A_SUMDATA2_CUS_Reserve2_29 "客户预留数据";
CM_ SG_ 2339569501 S2A_SUMDATA2_CUS_Reserve3_29 "客户预留数据";
CM_ SG_ 2339569501 S2A_SUMDATA2_CUS_Reserve4_29 "客户预留数据";
CM_ SG_ 2339569501 S2A_SUMDATA2_CUS_Reserve5_29 "客户预留数据";
CM_ SG_ 2339569501 S2A_SUMDATA2_CUS_Reserve6_29 "客户预留数据";
CM_ SG_ 2339569501 S2A_SUMDATA2_CUS_Reserve7_29 "客户预留数据";
CM_ SG_ 2339569501 S2A_SUMDATA2_CUS_Reserve8_29 "客户预留数据";
CM_ SG_ 2339569502 S2A_SUMDATA2_CUS_Reserve1_30 "客户预留数据";
CM_ SG_ 2339569502 S2A_SUMDATA2_CUS_Reserve2_30 "客户预留数据";
CM_ SG_ 2339569502 S2A_SUMDATA2_CUS_Reserve3_30 "客户预留数据";
CM_ SG_ 2339569502 S2A_SUMDATA2_CUS_Reserve4_30 "客户预留数据";
CM_ SG_ 2339569502 S2A_SUMDATA2_CUS_Reserve5_30 "客户预留数据";
CM_ SG_ 2339569502 S2A_SUMDATA2_CUS_Reserve6_30 "客户预留数据";
CM_ SG_ 2339569502 S2A_SUMDATA2_CUS_Reserve7_30 "客户预留数据";
CM_ SG_ 2339569502 S2A_SUMDATA2_CUS_Reserve8_30 "客户预留数据";
CM_ SG_ 2339569503 S2A_SUMDATA2_CUS_Reserve1_31 "客户预留数据";
CM_ SG_ 2339569503 S2A_SUMDATA2_CUS_Reserve2_31 "客户预留数据";
CM_ SG_ 2339569503 S2A_SUMDATA2_CUS_Reserve3_31 "客户预留数据";
CM_ SG_ 2339569503 S2A_SUMDATA2_CUS_Reserve4_31 "客户预留数据";
CM_ SG_ 2339569503 S2A_SUMDATA2_CUS_Reserve5_31 "客户预留数据";
CM_ SG_ 2339569503 S2A_SUMDATA2_CUS_Reserve6_31 "客户预留数据";
CM_ SG_ 2339569503 S2A_SUMDATA2_CUS_Reserve7_31 "客户预留数据";
CM_ SG_ 2339569503 S2A_SUMDATA2_CUS_Reserve8_31 "客户预留数据";
CM_ SG_ 2339569504 S2A_SUMDATA2_CUS_Reserve1_32 "客户预留数据";
CM_ SG_ 2339569504 S2A_SUMDATA2_CUS_Reserve2_32 "客户预留数据";
CM_ SG_ 2339569504 S2A_SUMDATA2_CUS_Reserve3_32 "客户预留数据";
CM_ SG_ 2339569504 S2A_SUMDATA2_CUS_Reserve4_32 "客户预留数据";
CM_ SG_ 2339569504 S2A_SUMDATA2_CUS_Reserve5_32 "客户预留数据";
CM_ SG_ 2339569504 S2A_SUMDATA2_CUS_Reserve6_32 "客户预留数据";
CM_ SG_ 2339569504 S2A_SUMDATA2_CUS_Reserve7_32 "客户预留数据";
CM_ SG_ 2339569504 S2A_SUMDATA2_CUS_Reserve8_32 "客户预留数据";
CM_ SG_ 2339569505 S2A_SUMDATA2_CUS_Reserve1_33 "客户预留数据";
CM_ SG_ 2339569505 S2A_SUMDATA2_CUS_Reserve2_33 "客户预留数据";
CM_ SG_ 2339569505 S2A_SUMDATA2_CUS_Reserve3_33 "客户预留数据";
CM_ SG_ 2339569505 S2A_SUMDATA2_CUS_Reserve4_33 "客户预留数据";
CM_ SG_ 2339569505 S2A_SUMDATA2_CUS_Reserve5_33 "客户预留数据";
CM_ SG_ 2339569505 S2A_SUMDATA2_CUS_Reserve6_33 "客户预留数据";
CM_ SG_ 2339569505 S2A_SUMDATA2_CUS_Reserve7_33 "客户预留数据";
CM_ SG_ 2339569505 S2A_SUMDATA2_CUS_Reserve8_33 "客户预留数据";
CM_ SG_ 2339569506 S2A_SUMDATA2_CUS_Reserve1_34 "客户预留数据";
CM_ SG_ 2339569506 S2A_SUMDATA2_CUS_Reserve2_34 "客户预留数据";
CM_ SG_ 2339569506 S2A_SUMDATA2_CUS_Reserve3_34 "客户预留数据";
CM_ SG_ 2339569506 S2A_SUMDATA2_CUS_Reserve4_34 "客户预留数据";
CM_ SG_ 2339569506 S2A_SUMDATA2_CUS_Reserve5_34 "客户预留数据";
CM_ SG_ 2339569506 S2A_SUMDATA2_CUS_Reserve6_34 "客户预留数据";
CM_ SG_ 2339569506 S2A_SUMDATA2_CUS_Reserve7_34 "客户预留数据";
CM_ SG_ 2339569506 S2A_SUMDATA2_CUS_Reserve8_34 "客户预留数据";
CM_ SG_ 2339569507 S2A_SUMDATA2_CUS_Reserve1_35 "客户预留数据";
CM_ SG_ 2339569507 S2A_SUMDATA2_CUS_Reserve2_35 "客户预留数据";
CM_ SG_ 2339569507 S2A_SUMDATA2_CUS_Reserve3_35 "客户预留数据";
CM_ SG_ 2339569507 S2A_SUMDATA2_CUS_Reserve4_35 "客户预留数据";
CM_ SG_ 2339569507 S2A_SUMDATA2_CUS_Reserve5_35 "客户预留数据";
CM_ SG_ 2339569507 S2A_SUMDATA2_CUS_Reserve6_35 "客户预留数据";
CM_ SG_ 2339569507 S2A_SUMDATA2_CUS_Reserve7_35 "客户预留数据";
CM_ SG_ 2339569507 S2A_SUMDATA2_CUS_Reserve8_35 "客户预留数据";
CM_ SG_ 2339569508 S2A_SUMDATA2_CUS_Reserve1_36 "客户预留数据";
CM_ SG_ 2339569508 S2A_SUMDATA2_CUS_Reserve2_36 "客户预留数据";
CM_ SG_ 2339569508 S2A_SUMDATA2_CUS_Reserve3_36 "客户预留数据";
CM_ SG_ 2339569508 S2A_SUMDATA2_CUS_Reserve4_36 "客户预留数据";
CM_ SG_ 2339569508 S2A_SUMDATA2_CUS_Reserve5_36 "客户预留数据";
CM_ SG_ 2339569508 S2A_SUMDATA2_CUS_Reserve6_36 "客户预留数据";
CM_ SG_ 2339569508 S2A_SUMDATA2_CUS_Reserve7_36 "客户预留数据";
CM_ SG_ 2339569508 S2A_SUMDATA2_CUS_Reserve8_36 "客户预留数据";
CM_ SG_ 2339569509 S2A_SUMDATA2_CUS_Reserve1_37 "客户预留数据";
CM_ SG_ 2339569509 S2A_SUMDATA2_CUS_Reserve2_37 "客户预留数据";
CM_ SG_ 2339569509 S2A_SUMDATA2_CUS_Reserve3_37 "客户预留数据";
CM_ SG_ 2339569509 S2A_SUMDATA2_CUS_Reserve4_37 "客户预留数据";
CM_ SG_ 2339569509 S2A_SUMDATA2_CUS_Reserve5_37 "客户预留数据";
CM_ SG_ 2339569509 S2A_SUMDATA2_CUS_Reserve6_37 "客户预留数据";
CM_ SG_ 2339569509 S2A_SUMDATA2_CUS_Reserve7_37 "客户预留数据";
CM_ SG_ 2339569509 S2A_SUMDATA2_CUS_Reserve8_37 "客户预留数据";
CM_ SG_ 2339569510 S2A_SUMDATA2_CUS_Reserve1_38 "客户预留数据";
CM_ SG_ 2339569510 S2A_SUMDATA2_CUS_Reserve2_38 "客户预留数据";
CM_ SG_ 2339569510 S2A_SUMDATA2_CUS_Reserve3_38 "客户预留数据";
CM_ SG_ 2339569510 S2A_SUMDATA2_CUS_Reserve4_38 "客户预留数据";
CM_ SG_ 2339569510 S2A_SUMDATA2_CUS_Reserve5_38 "客户预留数据";
CM_ SG_ 2339569510 S2A_SUMDATA2_CUS_Reserve6_38 "客户预留数据";
CM_ SG_ 2339569510 S2A_SUMDATA2_CUS_Reserve7_38 "客户预留数据";
CM_ SG_ 2339569510 S2A_SUMDATA2_CUS_Reserve8_38 "客户预留数据";
CM_ SG_ 2339569511 S2A_SUMDATA2_CUS_Reserve1_39 "客户预留数据";
CM_ SG_ 2339569511 S2A_SUMDATA2_CUS_Reserve2_39 "客户预留数据";
CM_ SG_ 2339569511 S2A_SUMDATA2_CUS_Reserve3_39 "客户预留数据";
CM_ SG_ 2339569511 S2A_SUMDATA2_CUS_Reserve4_39 "客户预留数据";
CM_ SG_ 2339569511 S2A_SUMDATA2_CUS_Reserve5_39 "客户预留数据";
CM_ SG_ 2339569511 S2A_SUMDATA2_CUS_Reserve6_39 "客户预留数据";
CM_ SG_ 2339569511 S2A_SUMDATA2_CUS_Reserve7_39 "客户预留数据";
CM_ SG_ 2339569511 S2A_SUMDATA2_CUS_Reserve8_39 "客户预留数据";
CM_ SG_ 2339569512 S2A_SUMDATA2_CUS_Reserve1_40 "客户预留数据";
CM_ SG_ 2339569512 S2A_SUMDATA2_CUS_Reserve2_40 "客户预留数据";
CM_ SG_ 2339569512 S2A_SUMDATA2_CUS_Reserve3_40 "客户预留数据";
CM_ SG_ 2339569512 S2A_SUMDATA2_CUS_Reserve4_40 "客户预留数据";
CM_ SG_ 2339569512 S2A_SUMDATA2_CUS_Reserve5_40 "客户预留数据";
CM_ SG_ 2339569512 S2A_SUMDATA2_CUS_Reserve6_40 "客户预留数据";
CM_ SG_ 2339569512 S2A_SUMDATA2_CUS_Reserve7_40 "客户预留数据";
CM_ SG_ 2339569512 S2A_SUMDATA2_CUS_Reserve8_40 "客户预留数据";
CM_ SG_ 2339569513 S2A_SUMDATA2_CUS_Reserve1_41 "客户预留数据";
CM_ SG_ 2339569513 S2A_SUMDATA2_CUS_Reserve2_41 "客户预留数据";
CM_ SG_ 2339569513 S2A_SUMDATA2_CUS_Reserve3_41 "客户预留数据";
CM_ SG_ 2339569513 S2A_SUMDATA2_CUS_Reserve4_41 "客户预留数据";
CM_ SG_ 2339569513 S2A_SUMDATA2_CUS_Reserve5_41 "客户预留数据";
CM_ SG_ 2339569513 S2A_SUMDATA2_CUS_Reserve6_41 "客户预留数据";
CM_ SG_ 2339569513 S2A_SUMDATA2_CUS_Reserve7_41 "客户预留数据";
CM_ SG_ 2339569513 S2A_SUMDATA2_CUS_Reserve8_41 "客户预留数据";
CM_ SG_ 2339569514 S2A_SUMDATA2_CUS_Reserve1_42 "客户预留数据";
CM_ SG_ 2339569514 S2A_SUMDATA2_CUS_Reserve2_42 "客户预留数据";
CM_ SG_ 2339569514 S2A_SUMDATA2_CUS_Reserve3_42 "客户预留数据";
CM_ SG_ 2339569514 S2A_SUMDATA2_CUS_Reserve4_42 "客户预留数据";
CM_ SG_ 2339569514 S2A_SUMDATA2_CUS_Reserve5_42 "客户预留数据";
CM_ SG_ 2339569514 S2A_SUMDATA2_CUS_Reserve6_42 "客户预留数据";
CM_ SG_ 2339569514 S2A_SUMDATA2_CUS_Reserve7_42 "客户预留数据";
CM_ SG_ 2339569514 S2A_SUMDATA2_CUS_Reserve8_42 "客户预留数据";
CM_ SG_ 2339569515 S2A_SUMDATA2_CUS_Reserve1_43 "客户预留数据";
CM_ SG_ 2339569515 S2A_SUMDATA2_CUS_Reserve2_43 "客户预留数据";
CM_ SG_ 2339569515 S2A_SUMDATA2_CUS_Reserve3_43 "客户预留数据";
CM_ SG_ 2339569515 S2A_SUMDATA2_CUS_Reserve4_43 "客户预留数据";
CM_ SG_ 2339569515 S2A_SUMDATA2_CUS_Reserve5_43 "客户预留数据";
CM_ SG_ 2339569515 S2A_SUMDATA2_CUS_Reserve6_43 "客户预留数据";
CM_ SG_ 2339569515 S2A_SUMDATA2_CUS_Reserve7_43 "客户预留数据";
CM_ SG_ 2339569515 S2A_SUMDATA2_CUS_Reserve8_43 "客户预留数据";
CM_ SG_ 2339569516 S2A_SUMDATA2_CUS_Reserve1_44 "客户预留数据";
CM_ SG_ 2339569516 S2A_SUMDATA2_CUS_Reserve2_44 "客户预留数据";
CM_ SG_ 2339569516 S2A_SUMDATA2_CUS_Reserve3_44 "客户预留数据";
CM_ SG_ 2339569516 S2A_SUMDATA2_CUS_Reserve4_44 "客户预留数据";
CM_ SG_ 2339569516 S2A_SUMDATA2_CUS_Reserve5_44 "客户预留数据";
CM_ SG_ 2339569516 S2A_SUMDATA2_CUS_Reserve6_44 "客户预留数据";
CM_ SG_ 2339569516 S2A_SUMDATA2_CUS_Reserve7_44 "客户预留数据";
CM_ SG_ 2339569516 S2A_SUMDATA2_CUS_Reserve8_44 "客户预留数据";
CM_ SG_ 2339569517 S2A_SUMDATA2_CUS_Reserve1_45 "客户预留数据";
CM_ SG_ 2339569517 S2A_SUMDATA2_CUS_Reserve2_45 "客户预留数据";
CM_ SG_ 2339569517 S2A_SUMDATA2_CUS_Reserve3_45 "客户预留数据";
CM_ SG_ 2339569517 S2A_SUMDATA2_CUS_Reserve4_45 "客户预留数据";
CM_ SG_ 2339569517 S2A_SUMDATA2_CUS_Reserve5_45 "客户预留数据";
CM_ SG_ 2339569517 S2A_SUMDATA2_CUS_Reserve6_45 "客户预留数据";
CM_ SG_ 2339569517 S2A_SUMDATA2_CUS_Reserve7_45 "客户预留数据";
CM_ SG_ 2339569517 S2A_SUMDATA2_CUS_Reserve8_45 "客户预留数据";
CM_ SG_ 2339569518 S2A_SUMDATA2_CUS_Reserve1_46 "客户预留数据";
CM_ SG_ 2339569518 S2A_SUMDATA2_CUS_Reserve2_46 "客户预留数据";
CM_ SG_ 2339569518 S2A_SUMDATA2_CUS_Reserve3_46 "客户预留数据";
CM_ SG_ 2339569518 S2A_SUMDATA2_CUS_Reserve4_46 "客户预留数据";
CM_ SG_ 2339569518 S2A_SUMDATA2_CUS_Reserve5_46 "客户预留数据";
CM_ SG_ 2339569518 S2A_SUMDATA2_CUS_Reserve6_46 "客户预留数据";
CM_ SG_ 2339569518 S2A_SUMDATA2_CUS_Reserve7_46 "客户预留数据";
CM_ SG_ 2339569518 S2A_SUMDATA2_CUS_Reserve8_46 "客户预留数据";
CM_ SG_ 2339569519 S2A_SUMDATA2_CUS_Reserve1_47 "客户预留数据";
CM_ SG_ 2339569519 S2A_SUMDATA2_CUS_Reserve2_47 "客户预留数据";
CM_ SG_ 2339569519 S2A_SUMDATA2_CUS_Reserve3_47 "客户预留数据";
CM_ SG_ 2339569519 S2A_SUMDATA2_CUS_Reserve4_47 "客户预留数据";
CM_ SG_ 2339569519 S2A_SUMDATA2_CUS_Reserve5_47 "客户预留数据";
CM_ SG_ 2339569519 S2A_SUMDATA2_CUS_Reserve6_47 "客户预留数据";
CM_ SG_ 2339569519 S2A_SUMDATA2_CUS_Reserve7_47 "客户预留数据";
CM_ SG_ 2339569519 S2A_SUMDATA2_CUS_Reserve8_47 "客户预留数据";
CM_ SG_ 2339569520 S2A_SUMDATA2_CUS_Reserve1_48 "客户预留数据";
CM_ SG_ 2339569520 S2A_SUMDATA2_CUS_Reserve2_48 "客户预留数据";
CM_ SG_ 2339569520 S2A_SUMDATA2_CUS_Reserve3_48 "客户预留数据";
CM_ SG_ 2339569520 S2A_SUMDATA2_CUS_Reserve4_48 "客户预留数据";
CM_ SG_ 2339569520 S2A_SUMDATA2_CUS_Reserve5_48 "客户预留数据";
CM_ SG_ 2339569520 S2A_SUMDATA2_CUS_Reserve6_48 "客户预留数据";
CM_ SG_ 2339569520 S2A_SUMDATA2_CUS_Reserve7_48 "客户预留数据";
CM_ SG_ 2339569520 S2A_SUMDATA2_CUS_Reserve8_48 "客户预留数据";
CM_ SG_ 2339569521 S2A_SUMDATA2_CUS_Reserve1_49 "客户预留数据";
CM_ SG_ 2339569521 S2A_SUMDATA2_CUS_Reserve2_49 "客户预留数据";
CM_ SG_ 2339569521 S2A_SUMDATA2_CUS_Reserve3_49 "客户预留数据";
CM_ SG_ 2339569521 S2A_SUMDATA2_CUS_Reserve4_49 "客户预留数据";
CM_ SG_ 2339569521 S2A_SUMDATA2_CUS_Reserve5_49 "客户预留数据";
CM_ SG_ 2339569521 S2A_SUMDATA2_CUS_Reserve6_49 "客户预留数据";
CM_ SG_ 2339569521 S2A_SUMDATA2_CUS_Reserve7_49 "客户预留数据";
CM_ SG_ 2339569521 S2A_SUMDATA2_CUS_Reserve8_49 "客户预留数据";
CM_ SG_ 2339569522 S2A_SUMDATA2_CUS_Reserve1_50 "客户预留数据";
CM_ SG_ 2339569522 S2A_SUMDATA2_CUS_Reserve2_50 "客户预留数据";
CM_ SG_ 2339569522 S2A_SUMDATA2_CUS_Reserve3_50 "客户预留数据";
CM_ SG_ 2339569522 S2A_SUMDATA2_CUS_Reserve4_50 "客户预留数据";
CM_ SG_ 2339569522 S2A_SUMDATA2_CUS_Reserve5_50 "客户预留数据";
CM_ SG_ 2339569522 S2A_SUMDATA2_CUS_Reserve6_50 "客户预留数据";
CM_ SG_ 2339569522 S2A_SUMDATA2_CUS_Reserve7_50 "客户预留数据";
CM_ SG_ 2339569522 S2A_SUMDATA2_CUS_Reserve8_50 "客户预留数据";
CM_ SG_ 2339569523 S2A_SUMDATA2_CUS_Reserve1_51 "客户预留数据";
CM_ SG_ 2339569523 S2A_SUMDATA2_CUS_Reserve2_51 "客户预留数据";
CM_ SG_ 2339569523 S2A_SUMDATA2_CUS_Reserve3_51 "客户预留数据";
CM_ SG_ 2339569523 S2A_SUMDATA2_CUS_Reserve4_51 "客户预留数据";
CM_ SG_ 2339569523 S2A_SUMDATA2_CUS_Reserve5_51 "客户预留数据";
CM_ SG_ 2339569523 S2A_SUMDATA2_CUS_Reserve6_51 "客户预留数据";
CM_ SG_ 2339569523 S2A_SUMDATA2_CUS_Reserve7_51 "客户预留数据";
CM_ SG_ 2339569523 S2A_SUMDATA2_CUS_Reserve8_51 "客户预留数据";
CM_ SG_ 2339569524 S2A_SUMDATA2_CUS_Reserve1_52 "客户预留数据";
CM_ SG_ 2339569524 S2A_SUMDATA2_CUS_Reserve2_52 "客户预留数据";
CM_ SG_ 2339569524 S2A_SUMDATA2_CUS_Reserve3_52 "客户预留数据";
CM_ SG_ 2339569524 S2A_SUMDATA2_CUS_Reserve4_52 "客户预留数据";
CM_ SG_ 2339569524 S2A_SUMDATA2_CUS_Reserve5_52 "客户预留数据";
CM_ SG_ 2339569524 S2A_SUMDATA2_CUS_Reserve6_52 "客户预留数据";
CM_ SG_ 2339569524 S2A_SUMDATA2_CUS_Reserve7_52 "客户预留数据";
CM_ SG_ 2339569524 S2A_SUMDATA2_CUS_Reserve8_52 "客户预留数据";
CM_ SG_ 2339569525 S2A_SUMDATA2_CUS_Reserve1_53 "客户预留数据";
CM_ SG_ 2339569525 S2A_SUMDATA2_CUS_Reserve2_53 "客户预留数据";
CM_ SG_ 2339569525 S2A_SUMDATA2_CUS_Reserve3_53 "客户预留数据";
CM_ SG_ 2339569525 S2A_SUMDATA2_CUS_Reserve4_53 "客户预留数据";
CM_ SG_ 2339569525 S2A_SUMDATA2_CUS_Reserve5_53 "客户预留数据";
CM_ SG_ 2339569525 S2A_SUMDATA2_CUS_Reserve6_53 "客户预留数据";
CM_ SG_ 2339569525 S2A_SUMDATA2_CUS_Reserve7_53 "客户预留数据";
CM_ SG_ 2339569525 S2A_SUMDATA2_CUS_Reserve8_53 "客户预留数据";
CM_ SG_ 2339569526 S2A_SUMDATA2_CUS_Reserve1_54 "客户预留数据";
CM_ SG_ 2339569526 S2A_SUMDATA2_CUS_Reserve2_54 "客户预留数据";
CM_ SG_ 2339569526 S2A_SUMDATA2_CUS_Reserve3_54 "客户预留数据";
CM_ SG_ 2339569526 S2A_SUMDATA2_CUS_Reserve4_54 "客户预留数据";
CM_ SG_ 2339569526 S2A_SUMDATA2_CUS_Reserve5_54 "客户预留数据";
CM_ SG_ 2339569526 S2A_SUMDATA2_CUS_Reserve6_54 "客户预留数据";
CM_ SG_ 2339569526 S2A_SUMDATA2_CUS_Reserve7_54 "客户预留数据";
CM_ SG_ 2339569526 S2A_SUMDATA2_CUS_Reserve8_54 "客户预留数据";
CM_ SG_ 2339569527 S2A_SUMDATA2_CUS_Reserve1_55 "客户预留数据";
CM_ SG_ 2339569527 S2A_SUMDATA2_CUS_Reserve2_55 "客户预留数据";
CM_ SG_ 2339569527 S2A_SUMDATA2_CUS_Reserve3_55 "客户预留数据";
CM_ SG_ 2339569527 S2A_SUMDATA2_CUS_Reserve4_55 "客户预留数据";
CM_ SG_ 2339569527 S2A_SUMDATA2_CUS_Reserve5_55 "客户预留数据";
CM_ SG_ 2339569527 S2A_SUMDATA2_CUS_Reserve6_55 "客户预留数据";
CM_ SG_ 2339569527 S2A_SUMDATA2_CUS_Reserve7_55 "客户预留数据";
CM_ SG_ 2339569527 S2A_SUMDATA2_CUS_Reserve8_55 "客户预留数据";
CM_ SG_ 2339569528 S2A_SUMDATA2_CUS_Reserve1_56 "客户预留数据";
CM_ SG_ 2339569528 S2A_SUMDATA2_CUS_Reserve2_56 "客户预留数据";
CM_ SG_ 2339569528 S2A_SUMDATA2_CUS_Reserve3_56 "客户预留数据";
CM_ SG_ 2339569528 S2A_SUMDATA2_CUS_Reserve4_56 "客户预留数据";
CM_ SG_ 2339569528 S2A_SUMDATA2_CUS_Reserve5_56 "客户预留数据";
CM_ SG_ 2339569528 S2A_SUMDATA2_CUS_Reserve6_56 "客户预留数据";
CM_ SG_ 2339569528 S2A_SUMDATA2_CUS_Reserve7_56 "客户预留数据";
CM_ SG_ 2339569528 S2A_SUMDATA2_CUS_Reserve8_56 "客户预留数据";
CM_ SG_ 2339569529 S2A_SUMDATA2_CUS_Reserve1_57 "客户预留数据";
CM_ SG_ 2339569529 S2A_SUMDATA2_CUS_Reserve2_57 "客户预留数据";
CM_ SG_ 2339569529 S2A_SUMDATA2_CUS_Reserve3_57 "客户预留数据";
CM_ SG_ 2339569529 S2A_SUMDATA2_CUS_Reserve4_57 "客户预留数据";
CM_ SG_ 2339569529 S2A_SUMDATA2_CUS_Reserve5_57 "客户预留数据";
CM_ SG_ 2339569529 S2A_SUMDATA2_CUS_Reserve6_57 "客户预留数据";
CM_ SG_ 2339569529 S2A_SUMDATA2_CUS_Reserve7_57 "客户预留数据";
CM_ SG_ 2339569529 S2A_SUMDATA2_CUS_Reserve8_57 "客户预留数据";
CM_ SG_ 2339569530 S2A_SUMDATA2_CUS_Reserve1_58 "客户预留数据";
CM_ SG_ 2339569530 S2A_SUMDATA2_CUS_Reserve2_58 "客户预留数据";
CM_ SG_ 2339569530 S2A_SUMDATA2_CUS_Reserve3_58 "客户预留数据";
CM_ SG_ 2339569530 S2A_SUMDATA2_CUS_Reserve4_58 "客户预留数据";
CM_ SG_ 2339569530 S2A_SUMDATA2_CUS_Reserve5_58 "客户预留数据";
CM_ SG_ 2339569530 S2A_SUMDATA2_CUS_Reserve6_58 "客户预留数据";
CM_ SG_ 2339569530 S2A_SUMDATA2_CUS_Reserve7_58 "客户预留数据";
CM_ SG_ 2339569530 S2A_SUMDATA2_CUS_Reserve8_58 "客户预留数据";
CM_ SG_ 2339569531 S2A_SUMDATA2_CUS_Reserve1_59 "客户预留数据";
CM_ SG_ 2339569531 S2A_SUMDATA2_CUS_Reserve2_59 "客户预留数据";
CM_ SG_ 2339569531 S2A_SUMDATA2_CUS_Reserve3_59 "客户预留数据";
CM_ SG_ 2339569531 S2A_SUMDATA2_CUS_Reserve4_59 "客户预留数据";
CM_ SG_ 2339569531 S2A_SUMDATA2_CUS_Reserve5_59 "客户预留数据";
CM_ SG_ 2339569531 S2A_SUMDATA2_CUS_Reserve6_59 "客户预留数据";
CM_ SG_ 2339569531 S2A_SUMDATA2_CUS_Reserve7_59 "客户预留数据";
CM_ SG_ 2339569531 S2A_SUMDATA2_CUS_Reserve8_59 "客户预留数据";
CM_ SG_ 2339569532 S2A_SUMDATA2_CUS_Reserve1_60 "客户预留数据";
CM_ SG_ 2339569532 S2A_SUMDATA2_CUS_Reserve2_60 "客户预留数据";
CM_ SG_ 2339569532 S2A_SUMDATA2_CUS_Reserve3_60 "客户预留数据";
CM_ SG_ 2339569532 S2A_SUMDATA2_CUS_Reserve4_60 "客户预留数据";
CM_ SG_ 2339569532 S2A_SUMDATA2_CUS_Reserve5_60 "客户预留数据";
CM_ SG_ 2339569532 S2A_SUMDATA2_CUS_Reserve6_60 "客户预留数据";
CM_ SG_ 2339569532 S2A_SUMDATA2_CUS_Reserve7_60 "客户预留数据";
CM_ SG_ 2339569532 S2A_SUMDATA2_CUS_Reserve8_60 "客户预留数据";
CM_ SG_ 2339569533 S2A_SUMDATA2_CUS_Reserve1_61 "客户预留数据";
CM_ SG_ 2339569533 S2A_SUMDATA2_CUS_Reserve2_61 "客户预留数据";
CM_ SG_ 2339569533 S2A_SUMDATA2_CUS_Reserve3_61 "客户预留数据";
CM_ SG_ 2339569533 S2A_SUMDATA2_CUS_Reserve4_61 "客户预留数据";
CM_ SG_ 2339569533 S2A_SUMDATA2_CUS_Reserve5_61 "客户预留数据";
CM_ SG_ 2339569533 S2A_SUMDATA2_CUS_Reserve6_61 "客户预留数据";
CM_ SG_ 2339569533 S2A_SUMDATA2_CUS_Reserve7_61 "客户预留数据";
CM_ SG_ 2339569533 S2A_SUMDATA2_CUS_Reserve8_61 "客户预留数据";
CM_ SG_ 2339569534 S2A_SUMDATA2_CUS_Reserve1_62 "客户预留数据";
CM_ SG_ 2339569534 S2A_SUMDATA2_CUS_Reserve2_62 "客户预留数据";
CM_ SG_ 2339569534 S2A_SUMDATA2_CUS_Reserve3_62 "客户预留数据";
CM_ SG_ 2339569534 S2A_SUMDATA2_CUS_Reserve4_62 "客户预留数据";
CM_ SG_ 2339569534 S2A_SUMDATA2_CUS_Reserve5_62 "客户预留数据";
CM_ SG_ 2339569534 S2A_SUMDATA2_CUS_Reserve6_62 "客户预留数据";
CM_ SG_ 2339569534 S2A_SUMDATA2_CUS_Reserve7_62 "客户预留数据";
CM_ SG_ 2339569534 S2A_SUMDATA2_CUS_Reserve8_62 "客户预留数据";
CM_ SG_ 2339569535 S2A_SUMDATA2_CUS_Reserve1_63 "客户预留数据";
CM_ SG_ 2339569535 S2A_SUMDATA2_CUS_Reserve2_63 "客户预留数据";
CM_ SG_ 2339569535 S2A_SUMDATA2_CUS_Reserve3_63 "客户预留数据";
CM_ SG_ 2339569535 S2A_SUMDATA2_CUS_Reserve4_63 "客户预留数据";
CM_ SG_ 2339569535 S2A_SUMDATA2_CUS_Reserve5_63 "客户预留数据";
CM_ SG_ 2339569535 S2A_SUMDATA2_CUS_Reserve6_63 "客户预留数据";
CM_ SG_ 2339569535 S2A_SUMDATA2_CUS_Reserve7_63 "客户预留数据";
CM_ SG_ 2339569535 S2A_SUMDATA2_CUS_Reserve8_63 "客户预留数据";
CM_ SG_ 2339635009 S2A_SUMDATA3_CUS_Reserve1_01 "客户预留数据";
CM_ SG_ 2339635009 S2A_SUMDATA3_CUS_Reserve2_01 "客户预留数据";
CM_ SG_ 2339635009 S2A_SUMDATA3_CUS_Reserve3_01 "客户预留数据";
CM_ SG_ 2339635009 S2A_SUMDATA3_CUS_Reserve4_01 "客户预留数据";
CM_ SG_ 2339635009 S2A_SUMDATA3_CUS_Reserve5_01 "客户预留数据";
CM_ SG_ 2339635009 S2A_SUMDATA3_CUS_Reserve6_01 "客户预留数据";
CM_ SG_ 2339635009 S2A_SUMDATA3_CUS_Reserve7_01 "客户预留数据";
CM_ SG_ 2339635009 S2A_SUMDATA3_CUS_Reserve8_01 "客户预留数据";
CM_ SG_ 2339635010 S2A_SUMDATA3_CUS_Reserve1_02 "客户预留数据";
CM_ SG_ 2339635010 S2A_SUMDATA3_CUS_Reserve2_02 "客户预留数据";
CM_ SG_ 2339635010 S2A_SUMDATA3_CUS_Reserve3_02 "客户预留数据";
CM_ SG_ 2339635010 S2A_SUMDATA3_CUS_Reserve4_02 "客户预留数据";
CM_ SG_ 2339635010 S2A_SUMDATA3_CUS_Reserve5_02 "客户预留数据";
CM_ SG_ 2339635010 S2A_SUMDATA3_CUS_Reserve6_02 "客户预留数据";
CM_ SG_ 2339635010 S2A_SUMDATA3_CUS_Reserve7_02 "客户预留数据";
CM_ SG_ 2339635010 S2A_SUMDATA3_CUS_Reserve8_02 "客户预留数据";
CM_ SG_ 2339635011 S2A_SUMDATA3_CUS_Reserve1_03 "客户预留数据";
CM_ SG_ 2339635011 S2A_SUMDATA3_CUS_Reserve2_03 "客户预留数据";
CM_ SG_ 2339635011 S2A_SUMDATA3_CUS_Reserve3_03 "客户预留数据";
CM_ SG_ 2339635011 S2A_SUMDATA3_CUS_Reserve4_03 "客户预留数据";
CM_ SG_ 2339635011 S2A_SUMDATA3_CUS_Reserve5_03 "客户预留数据";
CM_ SG_ 2339635011 S2A_SUMDATA3_CUS_Reserve6_03 "客户预留数据";
CM_ SG_ 2339635011 S2A_SUMDATA3_CUS_Reserve7_03 "客户预留数据";
CM_ SG_ 2339635011 S2A_SUMDATA3_CUS_Reserve8_03 "客户预留数据";
CM_ SG_ 2339635012 S2A_SUMDATA3_CUS_Reserve1_04 "客户预留数据";
CM_ SG_ 2339635012 S2A_SUMDATA3_CUS_Reserve2_04 "客户预留数据";
CM_ SG_ 2339635012 S2A_SUMDATA3_CUS_Reserve3_04 "客户预留数据";
CM_ SG_ 2339635012 S2A_SUMDATA3_CUS_Reserve4_04 "客户预留数据";
CM_ SG_ 2339635012 S2A_SUMDATA3_CUS_Reserve5_04 "客户预留数据";
CM_ SG_ 2339635012 S2A_SUMDATA3_CUS_Reserve6_04 "客户预留数据";
CM_ SG_ 2339635012 S2A_SUMDATA3_CUS_Reserve7_04 "客户预留数据";
CM_ SG_ 2339635012 S2A_SUMDATA3_CUS_Reserve8_04 "客户预留数据";
CM_ SG_ 2339635013 S2A_SUMDATA3_CUS_Reserve1_05 "客户预留数据";
CM_ SG_ 2339635013 S2A_SUMDATA3_CUS_Reserve2_05 "客户预留数据";
CM_ SG_ 2339635013 S2A_SUMDATA3_CUS_Reserve3_05 "客户预留数据";
CM_ SG_ 2339635013 S2A_SUMDATA3_CUS_Reserve4_05 "客户预留数据";
CM_ SG_ 2339635013 S2A_SUMDATA3_CUS_Reserve5_05 "客户预留数据";
CM_ SG_ 2339635013 S2A_SUMDATA3_CUS_Reserve6_05 "客户预留数据";
CM_ SG_ 2339635013 S2A_SUMDATA3_CUS_Reserve7_05 "客户预留数据";
CM_ SG_ 2339635013 S2A_SUMDATA3_CUS_Reserve8_05 "客户预留数据";
CM_ SG_ 2339635014 S2A_SUMDATA3_CUS_Reserve1_06 "客户预留数据";
CM_ SG_ 2339635014 S2A_SUMDATA3_CUS_Reserve2_06 "客户预留数据";
CM_ SG_ 2339635014 S2A_SUMDATA3_CUS_Reserve3_06 "客户预留数据";
CM_ SG_ 2339635014 S2A_SUMDATA3_CUS_Reserve4_06 "客户预留数据";
CM_ SG_ 2339635014 S2A_SUMDATA3_CUS_Reserve5_06 "客户预留数据";
CM_ SG_ 2339635014 S2A_SUMDATA3_CUS_Reserve6_06 "客户预留数据";
CM_ SG_ 2339635014 S2A_SUMDATA3_CUS_Reserve7_06 "客户预留数据";
CM_ SG_ 2339635014 S2A_SUMDATA3_CUS_Reserve8_06 "客户预留数据";
CM_ SG_ 2339635015 S2A_SUMDATA3_CUS_Reserve1_07 "客户预留数据";
CM_ SG_ 2339635015 S2A_SUMDATA3_CUS_Reserve2_07 "客户预留数据";
CM_ SG_ 2339635015 S2A_SUMDATA3_CUS_Reserve3_07 "客户预留数据";
CM_ SG_ 2339635015 S2A_SUMDATA3_CUS_Reserve4_07 "客户预留数据";
CM_ SG_ 2339635015 S2A_SUMDATA3_CUS_Reserve5_07 "客户预留数据";
CM_ SG_ 2339635015 S2A_SUMDATA3_CUS_Reserve6_07 "客户预留数据";
CM_ SG_ 2339635015 S2A_SUMDATA3_CUS_Reserve7_07 "客户预留数据";
CM_ SG_ 2339635015 S2A_SUMDATA3_CUS_Reserve8_07 "客户预留数据";
CM_ SG_ 2339635016 S2A_SUMDATA3_CUS_Reserve1_08 "客户预留数据";
CM_ SG_ 2339635016 S2A_SUMDATA3_CUS_Reserve2_08 "客户预留数据";
CM_ SG_ 2339635016 S2A_SUMDATA3_CUS_Reserve3_08 "客户预留数据";
CM_ SG_ 2339635016 S2A_SUMDATA3_CUS_Reserve4_08 "客户预留数据";
CM_ SG_ 2339635016 S2A_SUMDATA3_CUS_Reserve5_08 "客户预留数据";
CM_ SG_ 2339635016 S2A_SUMDATA3_CUS_Reserve6_08 "客户预留数据";
CM_ SG_ 2339635016 S2A_SUMDATA3_CUS_Reserve7_08 "客户预留数据";
CM_ SG_ 2339635016 S2A_SUMDATA3_CUS_Reserve8_08 "客户预留数据";
CM_ SG_ 2339635017 S2A_SUMDATA3_CUS_Reserve1_09 "客户预留数据";
CM_ SG_ 2339635017 S2A_SUMDATA3_CUS_Reserve2_09 "客户预留数据";
CM_ SG_ 2339635017 S2A_SUMDATA3_CUS_Reserve3_09 "客户预留数据";
CM_ SG_ 2339635017 S2A_SUMDATA3_CUS_Reserve4_09 "客户预留数据";
CM_ SG_ 2339635017 S2A_SUMDATA3_CUS_Reserve5_09 "客户预留数据";
CM_ SG_ 2339635017 S2A_SUMDATA3_CUS_Reserve6_09 "客户预留数据";
CM_ SG_ 2339635017 S2A_SUMDATA3_CUS_Reserve7_09 "客户预留数据";
CM_ SG_ 2339635017 S2A_SUMDATA3_CUS_Reserve8_09 "客户预留数据";
CM_ SG_ 2339635018 S2A_SUMDATA3_CUS_Reserve1_10 "客户预留数据";
CM_ SG_ 2339635018 S2A_SUMDATA3_CUS_Reserve2_10 "客户预留数据";
CM_ SG_ 2339635018 S2A_SUMDATA3_CUS_Reserve3_10 "客户预留数据";
CM_ SG_ 2339635018 S2A_SUMDATA3_CUS_Reserve4_10 "客户预留数据";
CM_ SG_ 2339635018 S2A_SUMDATA3_CUS_Reserve5_10 "客户预留数据";
CM_ SG_ 2339635018 S2A_SUMDATA3_CUS_Reserve6_10 "客户预留数据";
CM_ SG_ 2339635018 S2A_SUMDATA3_CUS_Reserve7_10 "客户预留数据";
CM_ SG_ 2339635018 S2A_SUMDATA3_CUS_Reserve8_10 "客户预留数据";
CM_ SG_ 2339635019 S2A_SUMDATA3_CUS_Reserve1_11 "客户预留数据";
CM_ SG_ 2339635019 S2A_SUMDATA3_CUS_Reserve2_11 "客户预留数据";
CM_ SG_ 2339635019 S2A_SUMDATA3_CUS_Reserve3_11 "客户预留数据";
CM_ SG_ 2339635019 S2A_SUMDATA3_CUS_Reserve4_11 "客户预留数据";
CM_ SG_ 2339635019 S2A_SUMDATA3_CUS_Reserve5_11 "客户预留数据";
CM_ SG_ 2339635019 S2A_SUMDATA3_CUS_Reserve6_11 "客户预留数据";
CM_ SG_ 2339635019 S2A_SUMDATA3_CUS_Reserve7_11 "客户预留数据";
CM_ SG_ 2339635019 S2A_SUMDATA3_CUS_Reserve8_11 "客户预留数据";
CM_ SG_ 2339635020 S2A_SUMDATA3_CUS_Reserve1_12 "客户预留数据";
CM_ SG_ 2339635020 S2A_SUMDATA3_CUS_Reserve2_12 "客户预留数据";
CM_ SG_ 2339635020 S2A_SUMDATA3_CUS_Reserve3_12 "客户预留数据";
CM_ SG_ 2339635020 S2A_SUMDATA3_CUS_Reserve4_12 "客户预留数据";
CM_ SG_ 2339635020 S2A_SUMDATA3_CUS_Reserve5_12 "客户预留数据";
CM_ SG_ 2339635020 S2A_SUMDATA3_CUS_Reserve6_12 "客户预留数据";
CM_ SG_ 2339635020 S2A_SUMDATA3_CUS_Reserve7_12 "客户预留数据";
CM_ SG_ 2339635020 S2A_SUMDATA3_CUS_Reserve8_12 "客户预留数据";
CM_ SG_ 2339635021 S2A_SUMDATA3_CUS_Reserve1_13 "客户预留数据";
CM_ SG_ 2339635021 S2A_SUMDATA3_CUS_Reserve2_13 "客户预留数据";
CM_ SG_ 2339635021 S2A_SUMDATA3_CUS_Reserve3_13 "客户预留数据";
CM_ SG_ 2339635021 S2A_SUMDATA3_CUS_Reserve4_13 "客户预留数据";
CM_ SG_ 2339635021 S2A_SUMDATA3_CUS_Reserve5_13 "客户预留数据";
CM_ SG_ 2339635021 S2A_SUMDATA3_CUS_Reserve6_13 "客户预留数据";
CM_ SG_ 2339635021 S2A_SUMDATA3_CUS_Reserve7_13 "客户预留数据";
CM_ SG_ 2339635021 S2A_SUMDATA3_CUS_Reserve8_13 "客户预留数据";
CM_ SG_ 2339635022 S2A_SUMDATA3_CUS_Reserve1_14 "客户预留数据";
CM_ SG_ 2339635022 S2A_SUMDATA3_CUS_Reserve2_14 "客户预留数据";
CM_ SG_ 2339635022 S2A_SUMDATA3_CUS_Reserve3_14 "客户预留数据";
CM_ SG_ 2339635022 S2A_SUMDATA3_CUS_Reserve4_14 "客户预留数据";
CM_ SG_ 2339635022 S2A_SUMDATA3_CUS_Reserve5_14 "客户预留数据";
CM_ SG_ 2339635022 S2A_SUMDATA3_CUS_Reserve6_14 "客户预留数据";
CM_ SG_ 2339635022 S2A_SUMDATA3_CUS_Reserve7_14 "客户预留数据";
CM_ SG_ 2339635022 S2A_SUMDATA3_CUS_Reserve8_14 "客户预留数据";
CM_ SG_ 2339635023 S2A_SUMDATA3_CUS_Reserve1_15 "客户预留数据";
CM_ SG_ 2339635023 S2A_SUMDATA3_CUS_Reserve2_15 "客户预留数据";
CM_ SG_ 2339635023 S2A_SUMDATA3_CUS_Reserve3_15 "客户预留数据";
CM_ SG_ 2339635023 S2A_SUMDATA3_CUS_Reserve4_15 "客户预留数据";
CM_ SG_ 2339635023 S2A_SUMDATA3_CUS_Reserve5_15 "客户预留数据";
CM_ SG_ 2339635023 S2A_SUMDATA3_CUS_Reserve6_15 "客户预留数据";
CM_ SG_ 2339635023 S2A_SUMDATA3_CUS_Reserve7_15 "客户预留数据";
CM_ SG_ 2339635023 S2A_SUMDATA3_CUS_Reserve8_15 "客户预留数据";
CM_ SG_ 2339635024 S2A_SUMDATA3_CUS_Reserve1_16 "客户预留数据";
CM_ SG_ 2339635024 S2A_SUMDATA3_CUS_Reserve2_16 "客户预留数据";
CM_ SG_ 2339635024 S2A_SUMDATA3_CUS_Reserve3_16 "客户预留数据";
CM_ SG_ 2339635024 S2A_SUMDATA3_CUS_Reserve4_16 "客户预留数据";
CM_ SG_ 2339635024 S2A_SUMDATA3_CUS_Reserve5_16 "客户预留数据";
CM_ SG_ 2339635024 S2A_SUMDATA3_CUS_Reserve6_16 "客户预留数据";
CM_ SG_ 2339635024 S2A_SUMDATA3_CUS_Reserve7_16 "客户预留数据";
CM_ SG_ 2339635024 S2A_SUMDATA3_CUS_Reserve8_16 "客户预留数据";
CM_ SG_ 2339635025 S2A_SUMDATA3_CUS_Reserve1_17 "客户预留数据";
CM_ SG_ 2339635025 S2A_SUMDATA3_CUS_Reserve2_17 "客户预留数据";
CM_ SG_ 2339635025 S2A_SUMDATA3_CUS_Reserve3_17 "客户预留数据";
CM_ SG_ 2339635025 S2A_SUMDATA3_CUS_Reserve4_17 "客户预留数据";
CM_ SG_ 2339635025 S2A_SUMDATA3_CUS_Reserve5_17 "客户预留数据";
CM_ SG_ 2339635025 S2A_SUMDATA3_CUS_Reserve6_17 "客户预留数据";
CM_ SG_ 2339635025 S2A_SUMDATA3_CUS_Reserve7_17 "客户预留数据";
CM_ SG_ 2339635025 S2A_SUMDATA3_CUS_Reserve8_17 "客户预留数据";
CM_ SG_ 2339635026 S2A_SUMDATA3_CUS_Reserve1_18 "客户预留数据";
CM_ SG_ 2339635026 S2A_SUMDATA3_CUS_Reserve2_18 "客户预留数据";
CM_ SG_ 2339635026 S2A_SUMDATA3_CUS_Reserve3_18 "客户预留数据";
CM_ SG_ 2339635026 S2A_SUMDATA3_CUS_Reserve4_18 "客户预留数据";
CM_ SG_ 2339635026 S2A_SUMDATA3_CUS_Reserve5_18 "客户预留数据";
CM_ SG_ 2339635026 S2A_SUMDATA3_CUS_Reserve6_18 "客户预留数据";
CM_ SG_ 2339635026 S2A_SUMDATA3_CUS_Reserve7_18 "客户预留数据";
CM_ SG_ 2339635026 S2A_SUMDATA3_CUS_Reserve8_18 "客户预留数据";
CM_ SG_ 2339635027 S2A_SUMDATA3_CUS_Reserve1_19 "客户预留数据";
CM_ SG_ 2339635027 S2A_SUMDATA3_CUS_Reserve2_19 "客户预留数据";
CM_ SG_ 2339635027 S2A_SUMDATA3_CUS_Reserve3_19 "客户预留数据";
CM_ SG_ 2339635027 S2A_SUMDATA3_CUS_Reserve4_19 "客户预留数据";
CM_ SG_ 2339635027 S2A_SUMDATA3_CUS_Reserve5_19 "客户预留数据";
CM_ SG_ 2339635027 S2A_SUMDATA3_CUS_Reserve6_19 "客户预留数据";
CM_ SG_ 2339635027 S2A_SUMDATA3_CUS_Reserve7_19 "客户预留数据";
CM_ SG_ 2339635027 S2A_SUMDATA3_CUS_Reserve8_19 "客户预留数据";
CM_ SG_ 2339635028 S2A_SUMDATA3_CUS_Reserve1_20 "客户预留数据";
CM_ SG_ 2339635028 S2A_SUMDATA3_CUS_Reserve2_20 "客户预留数据";
CM_ SG_ 2339635028 S2A_SUMDATA3_CUS_Reserve3_20 "客户预留数据";
CM_ SG_ 2339635028 S2A_SUMDATA3_CUS_Reserve4_20 "客户预留数据";
CM_ SG_ 2339635028 S2A_SUMDATA3_CUS_Reserve5_20 "客户预留数据";
CM_ SG_ 2339635028 S2A_SUMDATA3_CUS_Reserve6_20 "客户预留数据";
CM_ SG_ 2339635028 S2A_SUMDATA3_CUS_Reserve7_20 "客户预留数据";
CM_ SG_ 2339635028 S2A_SUMDATA3_CUS_Reserve8_20 "客户预留数据";
CM_ SG_ 2339635029 S2A_SUMDATA3_CUS_Reserve1_21 "客户预留数据";
CM_ SG_ 2339635029 S2A_SUMDATA3_CUS_Reserve2_21 "客户预留数据";
CM_ SG_ 2339635029 S2A_SUMDATA3_CUS_Reserve3_21 "客户预留数据";
CM_ SG_ 2339635029 S2A_SUMDATA3_CUS_Reserve4_21 "客户预留数据";
CM_ SG_ 2339635029 S2A_SUMDATA3_CUS_Reserve5_21 "客户预留数据";
CM_ SG_ 2339635029 S2A_SUMDATA3_CUS_Reserve6_21 "客户预留数据";
CM_ SG_ 2339635029 S2A_SUMDATA3_CUS_Reserve7_21 "客户预留数据";
CM_ SG_ 2339635029 S2A_SUMDATA3_CUS_Reserve8_21 "客户预留数据";
CM_ SG_ 2339635030 S2A_SUMDATA3_CUS_Reserve1_22 "客户预留数据";
CM_ SG_ 2339635030 S2A_SUMDATA3_CUS_Reserve2_22 "客户预留数据";
CM_ SG_ 2339635030 S2A_SUMDATA3_CUS_Reserve3_22 "客户预留数据";
CM_ SG_ 2339635030 S2A_SUMDATA3_CUS_Reserve4_22 "客户预留数据";
CM_ SG_ 2339635030 S2A_SUMDATA3_CUS_Reserve5_22 "客户预留数据";
CM_ SG_ 2339635030 S2A_SUMDATA3_CUS_Reserve6_22 "客户预留数据";
CM_ SG_ 2339635030 S2A_SUMDATA3_CUS_Reserve7_22 "客户预留数据";
CM_ SG_ 2339635030 S2A_SUMDATA3_CUS_Reserve8_22 "客户预留数据";
CM_ SG_ 2339635031 S2A_SUMDATA3_CUS_Reserve1_23 "客户预留数据";
CM_ SG_ 2339635031 S2A_SUMDATA3_CUS_Reserve2_23 "客户预留数据";
CM_ SG_ 2339635031 S2A_SUMDATA3_CUS_Reserve3_23 "客户预留数据";
CM_ SG_ 2339635031 S2A_SUMDATA3_CUS_Reserve4_23 "客户预留数据";
CM_ SG_ 2339635031 S2A_SUMDATA3_CUS_Reserve5_23 "客户预留数据";
CM_ SG_ 2339635031 S2A_SUMDATA3_CUS_Reserve6_23 "客户预留数据";
CM_ SG_ 2339635031 S2A_SUMDATA3_CUS_Reserve7_23 "客户预留数据";
CM_ SG_ 2339635031 S2A_SUMDATA3_CUS_Reserve8_23 "客户预留数据";
CM_ SG_ 2339635032 S2A_SUMDATA3_CUS_Reserve1_24 "客户预留数据";
CM_ SG_ 2339635032 S2A_SUMDATA3_CUS_Reserve2_24 "客户预留数据";
CM_ SG_ 2339635032 S2A_SUMDATA3_CUS_Reserve3_24 "客户预留数据";
CM_ SG_ 2339635032 S2A_SUMDATA3_CUS_Reserve4_24 "客户预留数据";
CM_ SG_ 2339635032 S2A_SUMDATA3_CUS_Reserve5_24 "客户预留数据";
CM_ SG_ 2339635032 S2A_SUMDATA3_CUS_Reserve6_24 "客户预留数据";
CM_ SG_ 2339635032 S2A_SUMDATA3_CUS_Reserve7_24 "客户预留数据";
CM_ SG_ 2339635032 S2A_SUMDATA3_CUS_Reserve8_24 "客户预留数据";
CM_ SG_ 2339635033 S2A_SUMDATA3_CUS_Reserve1_25 "客户预留数据";
CM_ SG_ 2339635033 S2A_SUMDATA3_CUS_Reserve2_25 "客户预留数据";
CM_ SG_ 2339635033 S2A_SUMDATA3_CUS_Reserve3_25 "客户预留数据";
CM_ SG_ 2339635033 S2A_SUMDATA3_CUS_Reserve4_25 "客户预留数据";
CM_ SG_ 2339635033 S2A_SUMDATA3_CUS_Reserve5_25 "客户预留数据";
CM_ SG_ 2339635033 S2A_SUMDATA3_CUS_Reserve6_25 "客户预留数据";
CM_ SG_ 2339635033 S2A_SUMDATA3_CUS_Reserve7_25 "客户预留数据";
CM_ SG_ 2339635033 S2A_SUMDATA3_CUS_Reserve8_25 "客户预留数据";
CM_ SG_ 2339635034 S2A_SUMDATA3_CUS_Reserve1_26 "客户预留数据";
CM_ SG_ 2339635034 S2A_SUMDATA3_CUS_Reserve2_26 "客户预留数据";
CM_ SG_ 2339635034 S2A_SUMDATA3_CUS_Reserve3_26 "客户预留数据";
CM_ SG_ 2339635034 S2A_SUMDATA3_CUS_Reserve4_26 "客户预留数据";
CM_ SG_ 2339635034 S2A_SUMDATA3_CUS_Reserve5_26 "客户预留数据";
CM_ SG_ 2339635034 S2A_SUMDATA3_CUS_Reserve6_26 "客户预留数据";
CM_ SG_ 2339635034 S2A_SUMDATA3_CUS_Reserve7_26 "客户预留数据";
CM_ SG_ 2339635034 S2A_SUMDATA3_CUS_Reserve8_26 "客户预留数据";
CM_ SG_ 2339635035 S2A_SUMDATA3_CUS_Reserve1_27 "客户预留数据";
CM_ SG_ 2339635035 S2A_SUMDATA3_CUS_Reserve2_27 "客户预留数据";
CM_ SG_ 2339635035 S2A_SUMDATA3_CUS_Reserve3_27 "客户预留数据";
CM_ SG_ 2339635035 S2A_SUMDATA3_CUS_Reserve4_27 "客户预留数据";
CM_ SG_ 2339635035 S2A_SUMDATA3_CUS_Reserve5_27 "客户预留数据";
CM_ SG_ 2339635035 S2A_SUMDATA3_CUS_Reserve6_27 "客户预留数据";
CM_ SG_ 2339635035 S2A_SUMDATA3_CUS_Reserve7_27 "客户预留数据";
CM_ SG_ 2339635035 S2A_SUMDATA3_CUS_Reserve8_27 "客户预留数据";
CM_ SG_ 2339635036 S2A_SUMDATA3_CUS_Reserve1_28 "客户预留数据";
CM_ SG_ 2339635036 S2A_SUMDATA3_CUS_Reserve2_28 "客户预留数据";
CM_ SG_ 2339635036 S2A_SUMDATA3_CUS_Reserve3_28 "客户预留数据";
CM_ SG_ 2339635036 S2A_SUMDATA3_CUS_Reserve4_28 "客户预留数据";
CM_ SG_ 2339635036 S2A_SUMDATA3_CUS_Reserve5_28 "客户预留数据";
CM_ SG_ 2339635036 S2A_SUMDATA3_CUS_Reserve6_28 "客户预留数据";
CM_ SG_ 2339635036 S2A_SUMDATA3_CUS_Reserve7_28 "客户预留数据";
CM_ SG_ 2339635036 S2A_SUMDATA3_CUS_Reserve8_28 "客户预留数据";
VERSION ""

NS_ :

BS_:

BU_: MBMU PC SBMU IMM ETH DCDC LEMS

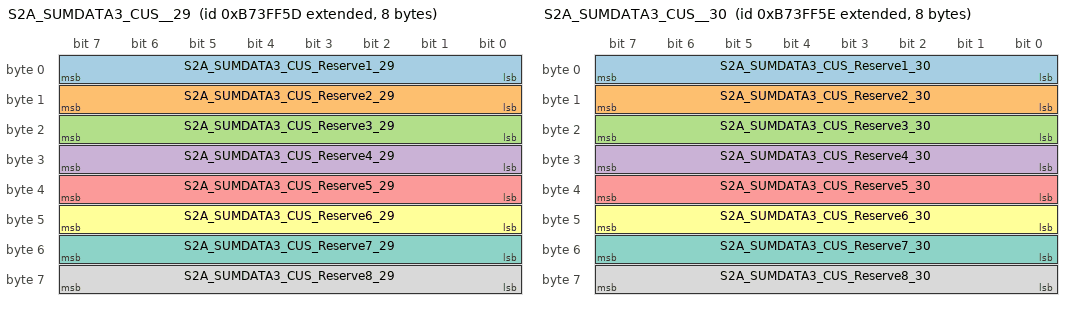
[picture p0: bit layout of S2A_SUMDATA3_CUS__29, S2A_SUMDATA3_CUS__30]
BO_ 2339635037 S2A_SUMDATA3_CUS__29: 8 SBMU
 SG_ S2A_SUMDATA3_CUS_Reserve1_29 : 0|8@1+ (1,0) [0|255] ""  PC,MBMU
 SG_ S2A_SUMDATA3_CUS_Reserve2_29 : 8|8@1+ (1,0) [0|255] ""  PC,MBMU
 SG_ S2A_SUMDATA3_CUS_Reserve3_29 : 16|8@1+ (1,0) [0|255] ""  PC,MBMU
 SG_ S2A_SUMDATA3_CUS_Reserve4_29 : 24|8@1+ (1,0) [0|255] ""  PC,MBMU
 SG_ S2A_SUMDATA3_CUS_Reserve5_29 : 32|8@1+ (1,0) [0|255] ""  PC,MBMU
 SG_ S2A_SUMDATA3_CUS_Reserve6_29 : 40|8@1+ (1,0) [0|255] ""  PC,MBMU
 SG_ S2A_SUMDATA3_CUS_Reserve7_29 : 48|8@1+ (1,0) [0|255] ""  PC,MBMU
 SG_ S2A_SUMDATA3_CUS_Reserve8_29 : 56|8@1+ (1,0) [0|255] ""  PC,MBMU

BO_ 2339635038 S2A_SUMDATA3_CUS__30: 8 SBMU
 SG_ S2A_SUMDATA3_CUS_Reserve1_30 : 0|8@1+ (1,0) [0|255] ""  PC,MBMU
 SG_ S2A_SUMDATA3_CUS_Reserve2_30 : 8|8@1+ (1,0) [0|255] ""  PC,MBMU
 SG_ S2A_SUMDATA3_CUS_Reserve3_30 : 16|8@1+ (1,0) [0|255] ""  PC,MBMU
 SG_ S2A_SUMDATA3_CUS_Reserve4_30 : 24|8@1+ (1,0) [0|255] ""  PC,MBMU
 SG_ S2A_SUMDATA3_CUS_Reserve5_30 : 32|8@1+ (1,0) [0|255] ""  PC,MBMU
 SG_ S2A_SUMDATA3_CUS_Reserve6_30 : 40|8@1+ (1,0) [0|255] ""  PC,MBMU
 SG_ S2A_SUMDATA3_CUS_Reserve7_30 : 48|8@1+ (1,0) [0|255] ""  PC,MBMU
 SG_ S2A_SUMDATA3_CUS_Reserve8_30 : 56|8@1+ (1,0) [0|255] ""  PC,MBMU

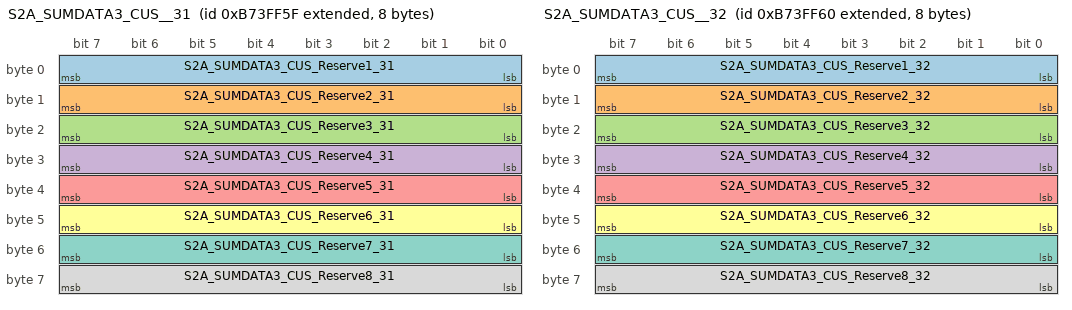
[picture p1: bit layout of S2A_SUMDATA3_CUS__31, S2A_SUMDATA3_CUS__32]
BO_ 2339635039 S2A_SUMDATA3_CUS__31: 8 SBMU
 SG_ S2A_SUMDATA3_CUS_Reserve1_31 : 0|8@1+ (1,0) [0|255] ""  PC,MBMU
 SG_ S2A_SUMDATA3_CUS_Reserve2_31 : 8|8@1+ (1,0) [0|255] ""  PC,MBMU
 SG_ S2A_SUMDATA3_CUS_Reserve3_31 : 16|8@1+ (1,0) [0|255] ""  PC,MBMU
 SG_ S2A_SUMDATA3_CUS_Reserve4_31 : 24|8@1+ (1,0) [0|255] ""  PC,MBMU
 SG_ S2A_SUMDATA3_CUS_Reserve5_31 : 32|8@1+ (1,0) [0|255] ""  PC,MBMU
 SG_ S2A_SUMDATA3_CUS_Reserve6_31 : 40|8@1+ (1,0) [0|255] ""  PC,MBMU
 SG_ S2A_SUMDATA3_CUS_Reserve7_31 : 48|8@1+ (1,0) [0|255] ""  PC,MBMU
 SG_ S2A_SUMDATA3_CUS_Reserve8_31 : 56|8@1+ (1,0) [0|255] ""  PC,MBMU

BO_ 2339635040 S2A_SUMDATA3_CUS__32: 8 SBMU
 SG_ S2A_SUMDATA3_CUS_Reserve1_32 : 0|8@1+ (1,0) [0|255] ""  PC,MBMU
 SG_ S2A_SUMDATA3_CUS_Reserve2_32 : 8|8@1+ (1,0) [0|255] ""  PC,MBMU
 SG_ S2A_SUMDATA3_CUS_Reserve3_32 : 16|8@1+ (1,0) [0|255] ""  PC,MBMU
 SG_ S2A_SUMDATA3_CUS_Reserve4_32 : 24|8@1+ (1,0) [0|255] ""  PC,MBMU
 SG_ S2A_SUMDATA3_CUS_Reserve5_32 : 32|8@1+ (1,0) [0|255] ""  PC,MBMU
 SG_ S2A_SUMDATA3_CUS_Reserve6_32 : 40|8@1+ (1,0) [0|255] ""  PC,MBMU
 SG_ S2A_SUMDATA3_CUS_Reserve7_32 : 48|8@1+ (1,0) [0|255] ""  PC,MBMU
 SG_ S2A_SUMDATA3_CUS_Reserve8_32 : 56|8@1+ (1,0) [0|255] ""  PC,MBMU

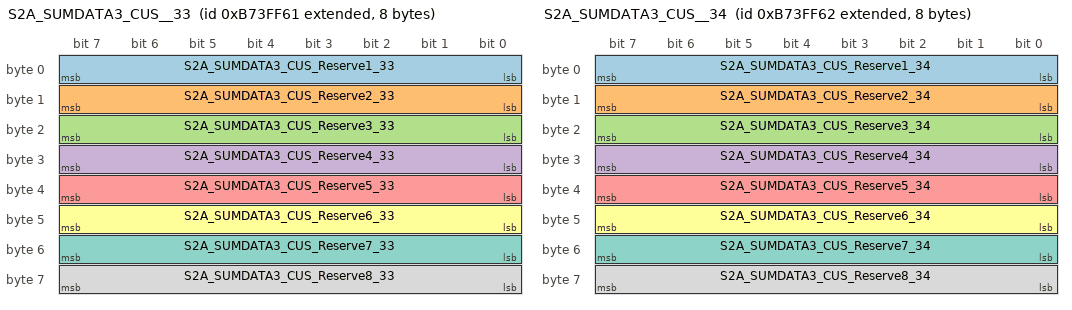
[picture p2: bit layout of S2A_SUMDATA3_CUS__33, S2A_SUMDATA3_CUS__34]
BO_ 2339635041 S2A_SUMDATA3_CUS__33: 8 SBMU
 SG_ S2A_SUMDATA3_CUS_Reserve1_33 : 0|8@1+ (1,0) [0|255] ""  PC,MBMU
 SG_ S2A_SUMDATA3_CUS_Reserve2_33 : 8|8@1+ (1,0) [0|255] ""  PC,MBMU
 SG_ S2A_SUMDATA3_CUS_Reserve3_33 : 16|8@1+ (1,0) [0|255] ""  PC,MBMU
 SG_ S2A_SUMDATA3_CUS_Reserve4_33 : 24|8@1+ (1,0) [0|255] ""  PC,MBMU
 SG_ S2A_SUMDATA3_CUS_Reserve5_33 : 32|8@1+ (1,0) [0|255] ""  PC,MBMU
 SG_ S2A_SUMDATA3_CUS_Reserve6_33 : 40|8@1+ (1,0) [0|255] ""  PC,MBMU
 SG_ S2A_SUMDATA3_CUS_Reserve7_33 : 48|8@1+ (1,0) [0|255] ""  PC,MBMU
 SG_ S2A_SUMDATA3_CUS_Reserve8_33 : 56|8@1+ (1,0) [0|255] ""  PC,MBMU

BO_ 2339635042 S2A_SUMDATA3_CUS__34: 8 SBMU
 SG_ S2A_SUMDATA3_CUS_Reserve1_34 : 0|8@1+ (1,0) [0|255] ""  PC,MBMU
 SG_ S2A_SUMDATA3_CUS_Reserve2_34 : 8|8@1+ (1,0) [0|255] ""  PC,MBMU
 SG_ S2A_SUMDATA3_CUS_Reserve3_34 : 16|8@1+ (1,0) [0|255] ""  PC,MBMU
 SG_ S2A_SUMDATA3_CUS_Reserve4_34 : 24|8@1+ (1,0) [0|255] ""  PC,MBMU
 SG_ S2A_SUMDATA3_CUS_Reserve5_34 : 32|8@1+ (1,0) [0|255] ""  PC,MBMU
 SG_ S2A_SUMDATA3_CUS_Reserve6_34 : 40|8@1+ (1,0) [0|255] ""  PC,MBMU
 SG_ S2A_SUMDATA3_CUS_Reserve7_34 : 48|8@1+ (1,0) [0|255] ""  PC,MBMU
 SG_ S2A_SUMDATA3_CUS_Reserve8_34 : 56|8@1+ (1,0) [0|255] ""  PC,MBMU

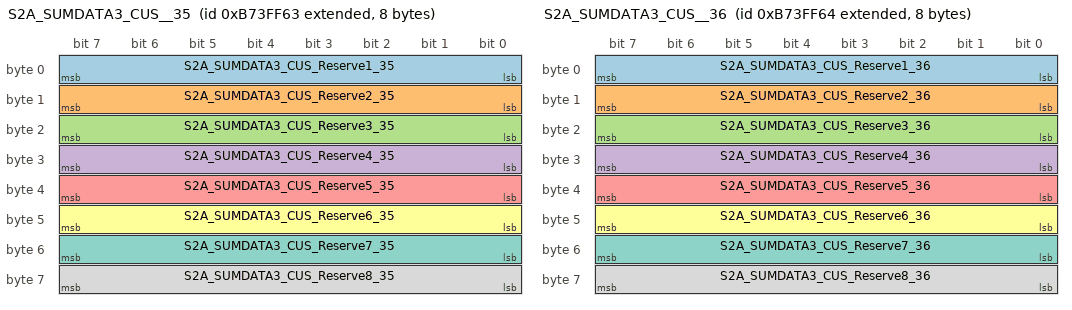
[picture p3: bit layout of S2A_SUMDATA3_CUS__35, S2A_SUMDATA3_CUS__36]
BO_ 2339635043 S2A_SUMDATA3_CUS__35: 8 SBMU
 SG_ S2A_SUMDATA3_CUS_Reserve1_35 : 0|8@1+ (1,0) [0|255] ""  PC,MBMU
 SG_ S2A_SUMDATA3_CUS_Reserve2_35 : 8|8@1+ (1,0) [0|255] ""  PC,MBMU
 SG_ S2A_SUMDATA3_CUS_Reserve3_35 : 16|8@1+ (1,0) [0|255] ""  PC,MBMU
 SG_ S2A_SUMDATA3_CUS_Reserve4_35 : 24|8@1+ (1,0) [0|255] ""  PC,MBMU
 SG_ S2A_SUMDATA3_CUS_Reserve5_35 : 32|8@1+ (1,0) [0|255] ""  PC,MBMU
 SG_ S2A_SUMDATA3_CUS_Reserve6_35 : 40|8@1+ (1,0) [0|255] ""  PC,MBMU
 SG_ S2A_SUMDATA3_CUS_Reserve7_35 : 48|8@1+ (1,0) [0|255] ""  PC,MBMU
 SG_ S2A_SUMDATA3_CUS_Reserve8_35 : 56|8@1+ (1,0) [0|255] ""  PC,MBMU

BO_ 2339635044 S2A_SUMDATA3_CUS__36: 8 SBMU
 SG_ S2A_SUMDATA3_CUS_Reserve1_36 : 0|8@1+ (1,0) [0|255] ""  PC,MBMU
 SG_ S2A_SUMDATA3_CUS_Reserve2_36 : 8|8@1+ (1,0) [0|255] ""  PC,MBMU
 SG_ S2A_SUMDATA3_CUS_Reserve3_36 : 16|8@1+ (1,0) [0|255] ""  PC,MBMU
 SG_ S2A_SUMDATA3_CUS_Reserve4_36 : 24|8@1+ (1,0) [0|255] ""  PC,MBMU
 SG_ S2A_SUMDATA3_CUS_Reserve5_36 : 32|8@1+ (1,0) [0|255] ""  PC,MBMU
 SG_ S2A_SUMDATA3_CUS_Reserve6_36 : 40|8@1+ (1,0) [0|255] ""  PC,MBMU
 SG_ S2A_SUMDATA3_CUS_Reserve7_36 : 48|8@1+ (1,0) [0|255] ""  PC,MBMU
 SG_ S2A_SUMDATA3_CUS_Reserve8_36 : 56|8@1+ (1,0) [0|255] ""  PC,MBMU

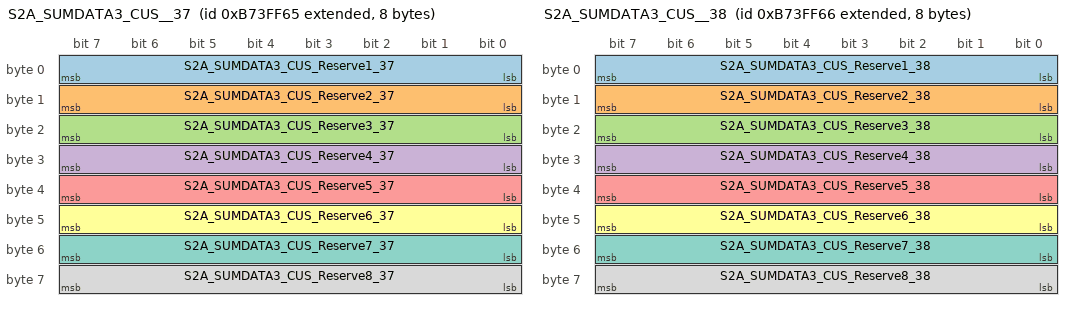
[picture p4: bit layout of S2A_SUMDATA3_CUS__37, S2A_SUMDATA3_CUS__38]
BO_ 2339635045 S2A_SUMDATA3_CUS__37: 8 SBMU
 SG_ S2A_SUMDATA3_CUS_Reserve1_37 : 0|8@1+ (1,0) [0|255] ""  PC,MBMU
 SG_ S2A_SUMDATA3_CUS_Reserve2_37 : 8|8@1+ (1,0) [0|255] ""  PC,MBMU
 SG_ S2A_SUMDATA3_CUS_Reserve3_37 : 16|8@1+ (1,0) [0|255] ""  PC,MBMU
 SG_ S2A_SUMDATA3_CUS_Reserve4_37 : 24|8@1+ (1,0) [0|255] ""  PC,MBMU
 SG_ S2A_SUMDATA3_CUS_Reserve5_37 : 32|8@1+ (1,0) [0|255] ""  PC,MBMU
 SG_ S2A_SUMDATA3_CUS_Reserve6_37 : 40|8@1+ (1,0) [0|255] ""  PC,MBMU
 SG_ S2A_SUMDATA3_CUS_Reserve7_37 : 48|8@1+ (1,0) [0|255] ""  PC,MBMU
 SG_ S2A_SUMDATA3_CUS_Reserve8_37 : 56|8@1+ (1,0) [0|255] ""  PC,MBMU

BO_ 2339635046 S2A_SUMDATA3_CUS__38: 8 SBMU
 SG_ S2A_SUMDATA3_CUS_Reserve1_38 : 0|8@1+ (1,0) [0|255] ""  PC,MBMU
 SG_ S2A_SUMDATA3_CUS_Reserve2_38 : 8|8@1+ (1,0) [0|255] ""  PC,MBMU
 SG_ S2A_SUMDATA3_CUS_Reserve3_38 : 16|8@1+ (1,0) [0|255] ""  PC,MBMU
 SG_ S2A_SUMDATA3_CUS_Reserve4_38 : 24|8@1+ (1,0) [0|255] ""  PC,MBMU
 SG_ S2A_SUMDATA3_CUS_Reserve5_38 : 32|8@1+ (1,0) [0|255] ""  PC,MBMU
 SG_ S2A_SUMDATA3_CUS_Reserve6_38 : 40|8@1+ (1,0) [0|255] ""  PC,MBMU
 SG_ S2A_SUMDATA3_CUS_Reserve7_38 : 48|8@1+ (1,0) [0|255] ""  PC,MBMU
 SG_ S2A_SUMDATA3_CUS_Reserve8_38 : 56|8@1+ (1,0) [0|255] ""  PC,MBMU

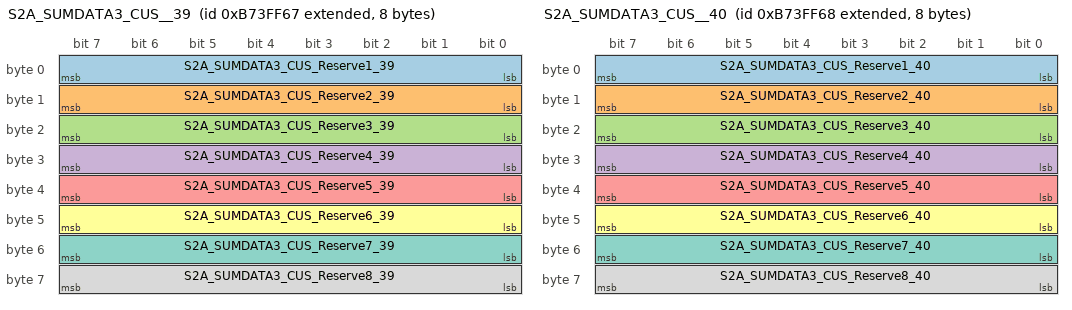
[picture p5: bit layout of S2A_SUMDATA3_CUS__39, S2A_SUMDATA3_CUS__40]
BO_ 2339635047 S2A_SUMDATA3_CUS__39: 8 SBMU
 SG_ S2A_SUMDATA3_CUS_Reserve1_39 : 0|8@1+ (1,0) [0|255] ""  PC,MBMU
 SG_ S2A_SUMDATA3_CUS_Reserve2_39 : 8|8@1+ (1,0) [0|255] ""  PC,MBMU
 SG_ S2A_SUMDATA3_CUS_Reserve3_39 : 16|8@1+ (1,0) [0|255] ""  PC,MBMU
 SG_ S2A_SUMDATA3_CUS_Reserve4_39 : 24|8@1+ (1,0) [0|255] ""  PC,MBMU
 SG_ S2A_SUMDATA3_CUS_Reserve5_39 : 32|8@1+ (1,0) [0|255] ""  PC,MBMU
 SG_ S2A_SUMDATA3_CUS_Reserve6_39 : 40|8@1+ (1,0) [0|255] ""  PC,MBMU
 SG_ S2A_SUMDATA3_CUS_Reserve7_39 : 48|8@1+ (1,0) [0|255] ""  PC,MBMU
 SG_ S2A_SUMDATA3_CUS_Reserve8_39 : 56|8@1+ (1,0) [0|255] ""  PC,MBMU

BO_ 2339635048 S2A_SUMDATA3_CUS__40: 8 SBMU
 SG_ S2A_SUMDATA3_CUS_Reserve1_40 : 0|8@1+ (1,0) [0|255] ""  PC,MBMU
 SG_ S2A_SUMDATA3_CUS_Reserve2_40 : 8|8@1+ (1,0) [0|255] ""  PC,MBMU
 SG_ S2A_SUMDATA3_CUS_Reserve3_40 : 16|8@1+ (1,0) [0|255] ""  PC,MBMU
 SG_ S2A_SUMDATA3_CUS_Reserve4_40 : 24|8@1+ (1,0) [0|255] ""  PC,MBMU
 SG_ S2A_SUMDATA3_CUS_Reserve5_40 : 32|8@1+ (1,0) [0|255] ""  PC,MBMU
 SG_ S2A_SUMDATA3_CUS_Reserve6_40 : 40|8@1+ (1,0) [0|255] ""  PC,MBMU
 SG_ S2A_SUMDATA3_CUS_Reserve7_40 : 48|8@1+ (1,0) [0|255] ""  PC,MBMU
 SG_ S2A_SUMDATA3_CUS_Reserve8_40 : 56|8@1+ (1,0) [0|255] ""  PC,MBMU

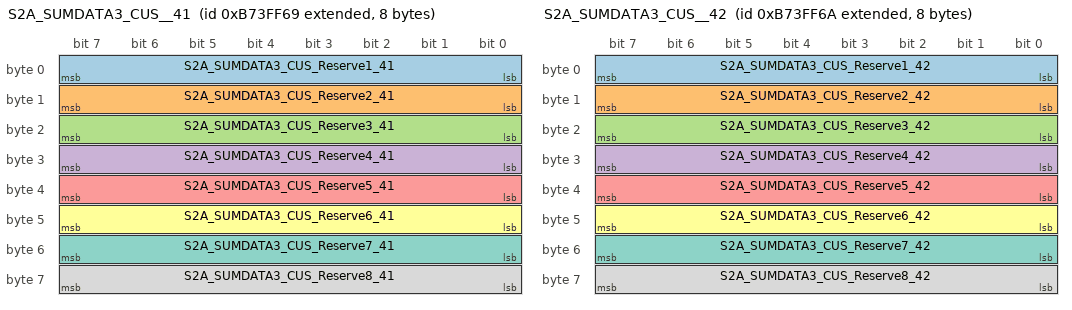
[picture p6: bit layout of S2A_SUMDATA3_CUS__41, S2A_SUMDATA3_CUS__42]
BO_ 2339635049 S2A_SUMDATA3_CUS__41: 8 SBMU
 SG_ S2A_SUMDATA3_CUS_Reserve1_41 : 0|8@1+ (1,0) [0|255] ""  PC,MBMU
 SG_ S2A_SUMDATA3_CUS_Reserve2_41 : 8|8@1+ (1,0) [0|255] ""  PC,MBMU
 SG_ S2A_SUMDATA3_CUS_Reserve3_41 : 16|8@1+ (1,0) [0|255] ""  PC,MBMU
 SG_ S2A_SUMDATA3_CUS_Reserve4_41 : 24|8@1+ (1,0) [0|255] ""  PC,MBMU
 SG_ S2A_SUMDATA3_CUS_Reserve5_41 : 32|8@1+ (1,0) [0|255] ""  PC,MBMU
 SG_ S2A_SUMDATA3_CUS_Reserve6_41 : 40|8@1+ (1,0) [0|255] ""  PC,MBMU
 SG_ S2A_SUMDATA3_CUS_Reserve7_41 : 48|8@1+ (1,0) [0|255] ""  PC,MBMU
 SG_ S2A_SUMDATA3_CUS_Reserve8_41 : 56|8@1+ (1,0) [0|255] ""  PC,MBMU

BO_ 2339635050 S2A_SUMDATA3_CUS__42: 8 SBMU
 SG_ S2A_SUMDATA3_CUS_Reserve1_42 : 0|8@1+ (1,0) [0|255] ""  PC,MBMU
 SG_ S2A_SUMDATA3_CUS_Reserve2_42 : 8|8@1+ (1,0) [0|255] ""  PC,MBMU
 SG_ S2A_SUMDATA3_CUS_Reserve3_42 : 16|8@1+ (1,0) [0|255] ""  PC,MBMU
 SG_ S2A_SUMDATA3_CUS_Reserve4_42 : 24|8@1+ (1,0) [0|255] ""  PC,MBMU
 SG_ S2A_SUMDATA3_CUS_Reserve5_42 : 32|8@1+ (1,0) [0|255] ""  PC,MBMU
 SG_ S2A_SUMDATA3_CUS_Reserve6_42 : 40|8@1+ (1,0) [0|255] ""  PC,MBMU
 SG_ S2A_SUMDATA3_CUS_Reserve7_42 : 48|8@1+ (1,0) [0|255] ""  PC,MBMU
 SG_ S2A_SUMDATA3_CUS_Reserve8_42 : 56|8@1+ (1,0) [0|255] ""  PC,MBMU

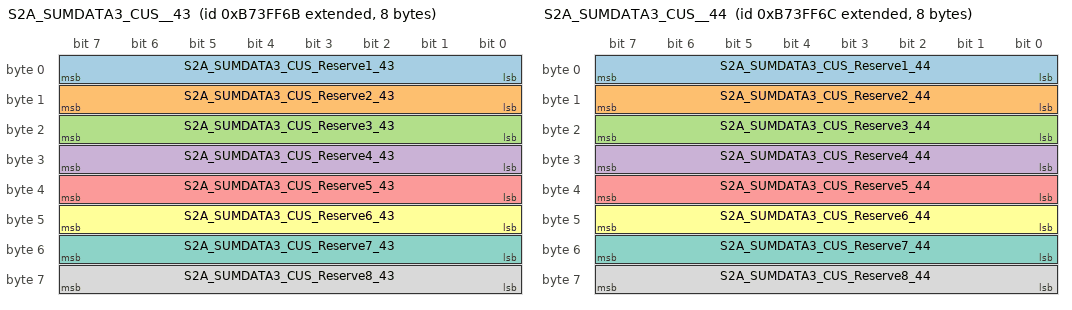
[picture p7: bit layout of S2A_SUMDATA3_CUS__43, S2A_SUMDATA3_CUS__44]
BO_ 2339635051 S2A_SUMDATA3_CUS__43: 8 SBMU
 SG_ S2A_SUMDATA3_CUS_Reserve1_43 : 0|8@1+ (1,0) [0|255] ""  PC,MBMU
 SG_ S2A_SUMDATA3_CUS_Reserve2_43 : 8|8@1+ (1,0) [0|255] ""  PC,MBMU
 SG_ S2A_SUMDATA3_CUS_Reserve3_43 : 16|8@1+ (1,0) [0|255] ""  PC,MBMU
 SG_ S2A_SUMDATA3_CUS_Reserve4_43 : 24|8@1+ (1,0) [0|255] ""  PC,MBMU
 SG_ S2A_SUMDATA3_CUS_Reserve5_43 : 32|8@1+ (1,0) [0|255] ""  PC,MBMU
 SG_ S2A_SUMDATA3_CUS_Reserve6_43 : 40|8@1+ (1,0) [0|255] ""  PC,MBMU
 SG_ S2A_SUMDATA3_CUS_Reserve7_43 : 48|8@1+ (1,0) [0|255] ""  PC,MBMU
 SG_ S2A_SUMDATA3_CUS_Reserve8_43 : 56|8@1+ (1,0) [0|255] ""  PC,MBMU

BO_ 2339635052 S2A_SUMDATA3_CUS__44: 8 SBMU
 SG_ S2A_SUMDATA3_CUS_Reserve1_44 : 0|8@1+ (1,0) [0|255] ""  PC,MBMU
 SG_ S2A_SUMDATA3_CUS_Reserve2_44 : 8|8@1+ (1,0) [0|255] ""  PC,MBMU
 SG_ S2A_SUMDATA3_CUS_Reserve3_44 : 16|8@1+ (1,0) [0|255] ""  PC,MBMU
 SG_ S2A_SUMDATA3_CUS_Reserve4_44 : 24|8@1+ (1,0) [0|255] ""  PC,MBMU
 SG_ S2A_SUMDATA3_CUS_Reserve5_44 : 32|8@1+ (1,0) [0|255] ""  PC,MBMU
 SG_ S2A_SUMDATA3_CUS_Reserve6_44 : 40|8@1+ (1,0) [0|255] ""  PC,MBMU
 SG_ S2A_SUMDATA3_CUS_Reserve7_44 : 48|8@1+ (1,0) [0|255] ""  PC,MBMU
 SG_ S2A_SUMDATA3_CUS_Reserve8_44 : 56|8@1+ (1,0) [0|255] ""  PC,MBMU

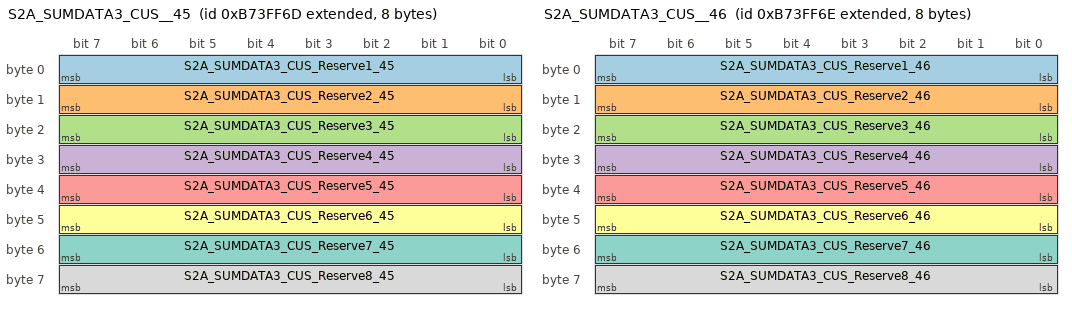
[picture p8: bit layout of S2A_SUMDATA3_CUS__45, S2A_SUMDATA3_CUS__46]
BO_ 2339635053 S2A_SUMDATA3_CUS__45: 8 SBMU
 SG_ S2A_SUMDATA3_CUS_Reserve1_45 : 0|8@1+ (1,0) [0|255] ""  PC,MBMU
 SG_ S2A_SUMDATA3_CUS_Reserve2_45 : 8|8@1+ (1,0) [0|255] ""  PC,MBMU
 SG_ S2A_SUMDATA3_CUS_Reserve3_45 : 16|8@1+ (1,0) [0|255] ""  PC,MBMU
 SG_ S2A_SUMDATA3_CUS_Reserve4_45 : 24|8@1+ (1,0) [0|255] ""  PC,MBMU
 SG_ S2A_SUMDATA3_CUS_Reserve5_45 : 32|8@1+ (1,0) [0|255] ""  PC,MBMU
 SG_ S2A_SUMDATA3_CUS_Reserve6_45 : 40|8@1+ (1,0) [0|255] ""  PC,MBMU
 SG_ S2A_SUMDATA3_CUS_Reserve7_45 : 48|8@1+ (1,0) [0|255] ""  PC,MBMU
 SG_ S2A_SUMDATA3_CUS_Reserve8_45 : 56|8@1+ (1,0) [0|255] ""  PC,MBMU

BO_ 2339635054 S2A_SUMDATA3_CUS__46: 8 SBMU
 SG_ S2A_SUMDATA3_CUS_Reserve1_46 : 0|8@1+ (1,0) [0|255] ""  PC,MBMU
 SG_ S2A_SUMDATA3_CUS_Reserve2_46 : 8|8@1+ (1,0) [0|255] ""  PC,MBMU
 SG_ S2A_SUMDATA3_CUS_Reserve3_46 : 16|8@1+ (1,0) [0|255] ""  PC,MBMU
 SG_ S2A_SUMDATA3_CUS_Reserve4_46 : 24|8@1+ (1,0) [0|255] ""  PC,MBMU
 SG_ S2A_SUMDATA3_CUS_Reserve5_46 : 32|8@1+ (1,0) [0|255] ""  PC,MBMU
 SG_ S2A_SUMDATA3_CUS_Reserve6_46 : 40|8@1+ (1,0) [0|255] ""  PC,MBMU
 SG_ S2A_SUMDATA3_CUS_Reserve7_46 : 48|8@1+ (1,0) [0|255] ""  PC,MBMU
 SG_ S2A_SUMDATA3_CUS_Reserve8_46 : 56|8@1+ (1,0) [0|255] ""  PC,MBMU

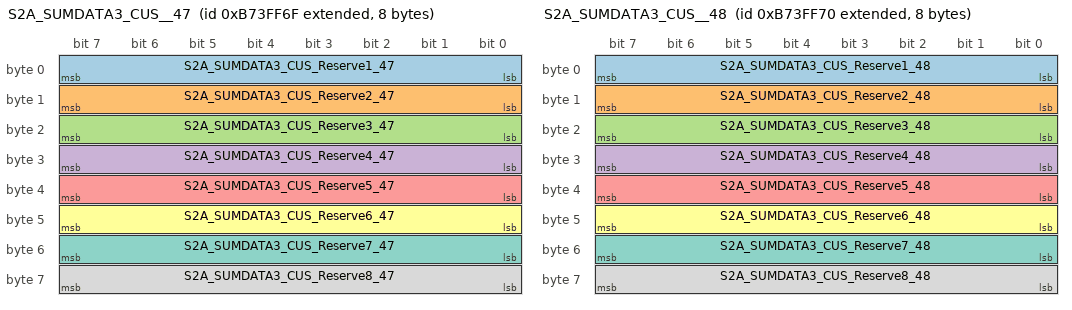
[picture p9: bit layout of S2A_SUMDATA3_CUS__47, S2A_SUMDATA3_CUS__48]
BO_ 2339635055 S2A_SUMDATA3_CUS__47: 8 SBMU
 SG_ S2A_SUMDATA3_CUS_Reserve1_47 : 0|8@1+ (1,0) [0|255] ""  PC,MBMU
 SG_ S2A_SUMDATA3_CUS_Reserve2_47 : 8|8@1+ (1,0) [0|255] ""  PC,MBMU
 SG_ S2A_SUMDATA3_CUS_Reserve3_47 : 16|8@1+ (1,0) [0|255] ""  PC,MBMU
 SG_ S2A_SUMDATA3_CUS_Reserve4_47 : 24|8@1+ (1,0) [0|255] ""  PC,MBMU
 SG_ S2A_SUMDATA3_CUS_Reserve5_47 : 32|8@1+ (1,0) [0|255] ""  PC,MBMU
 SG_ S2A_SUMDATA3_CUS_Reserve6_47 : 40|8@1+ (1,0) [0|255] ""  PC,MBMU
 SG_ S2A_SUMDATA3_CUS_Reserve7_47 : 48|8@1+ (1,0) [0|255] ""  PC,MBMU
 SG_ S2A_SUMDATA3_CUS_Reserve8_47 : 56|8@1+ (1,0) [0|255] ""  PC,MBMU

BO_ 2339635056 S2A_SUMDATA3_CUS__48: 8 SBMU
 SG_ S2A_SUMDATA3_CUS_Reserve1_48 : 0|8@1+ (1,0) [0|255] ""  PC,MBMU
 SG_ S2A_SUMDATA3_CUS_Reserve2_48 : 8|8@1+ (1,0) [0|255] ""  PC,MBMU
 SG_ S2A_SUMDATA3_CUS_Reserve3_48 : 16|8@1+ (1,0) [0|255] ""  PC,MBMU
 SG_ S2A_SUMDATA3_CUS_Reserve4_48 : 24|8@1+ (1,0) [0|255] ""  PC,MBMU
 SG_ S2A_SUMDATA3_CUS_Reserve5_48 : 32|8@1+ (1,0) [0|255] ""  PC,MBMU
 SG_ S2A_SUMDATA3_CUS_Reserve6_48 : 40|8@1+ (1,0) [0|255] ""  PC,MBMU
 SG_ S2A_SUMDATA3_CUS_Reserve7_48 : 48|8@1+ (1,0) [0|255] ""  PC,MBMU
 SG_ S2A_SUMDATA3_CUS_Reserve8_48 : 56|8@1+ (1,0) [0|255] ""  PC,MBMU

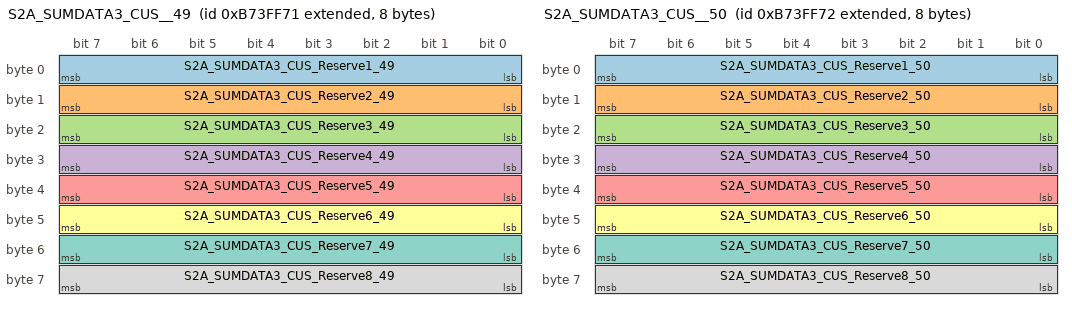
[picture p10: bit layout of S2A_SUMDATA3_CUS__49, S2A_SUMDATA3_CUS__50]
BO_ 2339635057 S2A_SUMDATA3_CUS__49: 8 SBMU
 SG_ S2A_SUMDATA3_CUS_Reserve1_49 : 0|8@1+ (1,0) [0|255] ""  PC,MBMU
 SG_ S2A_SUMDATA3_CUS_Reserve2_49 : 8|8@1+ (1,0) [0|255] ""  PC,MBMU
 SG_ S2A_SUMDATA3_CUS_Reserve3_49 : 16|8@1+ (1,0) [0|255] ""  PC,MBMU
 SG_ S2A_SUMDATA3_CUS_Reserve4_49 : 24|8@1+ (1,0) [0|255] ""  PC,MBMU
 SG_ S2A_SUMDATA3_CUS_Reserve5_49 : 32|8@1+ (1,0) [0|255] ""  PC,MBMU
 SG_ S2A_SUMDATA3_CUS_Reserve6_49 : 40|8@1+ (1,0) [0|255] ""  PC,MBMU
 SG_ S2A_SUMDATA3_CUS_Reserve7_49 : 48|8@1+ (1,0) [0|255] ""  PC,MBMU
 SG_ S2A_SUMDATA3_CUS_Reserve8_49 : 56|8@1+ (1,0) [0|255] ""  PC,MBMU

BO_ 2339635058 S2A_SUMDATA3_CUS__50: 8 SBMU
 SG_ S2A_SUMDATA3_CUS_Reserve1_50 : 0|8@1+ (1,0) [0|255] ""  PC,MBMU
 SG_ S2A_SUMDATA3_CUS_Reserve2_50 : 8|8@1+ (1,0) [0|255] ""  PC,MBMU
 SG_ S2A_SUMDATA3_CUS_Reserve3_50 : 16|8@1+ (1,0) [0|255] ""  PC,MBMU
 SG_ S2A_SUMDATA3_CUS_Reserve4_50 : 24|8@1+ (1,0) [0|255] ""  PC,MBMU
 SG_ S2A_SUMDATA3_CUS_Reserve5_50 : 32|8@1+ (1,0) [0|255] ""  PC,MBMU
 SG_ S2A_SUMDATA3_CUS_Reserve6_50 : 40|8@1+ (1,0) [0|255] ""  PC,MBMU
 SG_ S2A_SUMDATA3_CUS_Reserve7_50 : 48|8@1+ (1,0) [0|255] ""  PC,MBMU
 SG_ S2A_SUMDATA3_CUS_Reserve8_50 : 56|8@1+ (1,0) [0|255] ""  PC,MBMU

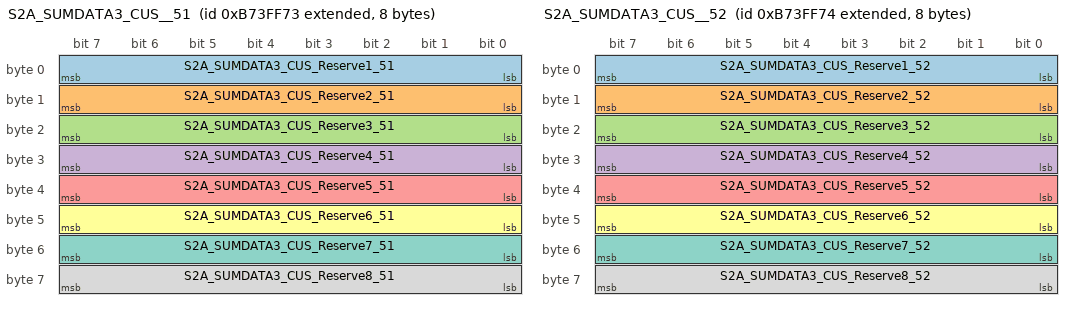
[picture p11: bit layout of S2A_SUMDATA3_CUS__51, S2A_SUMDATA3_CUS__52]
BO_ 2339635059 S2A_SUMDATA3_CUS__51: 8 SBMU
 SG_ S2A_SUMDATA3_CUS_Reserve1_51 : 0|8@1+ (1,0) [0|255] ""  PC,MBMU
 SG_ S2A_SUMDATA3_CUS_Reserve2_51 : 8|8@1+ (1,0) [0|255] ""  PC,MBMU
 SG_ S2A_SUMDATA3_CUS_Reserve3_51 : 16|8@1+ (1,0) [0|255] ""  PC,MBMU
 SG_ S2A_SUMDATA3_CUS_Reserve4_51 : 24|8@1+ (1,0) [0|255] ""  PC,MBMU
 SG_ S2A_SUMDATA3_CUS_Reserve5_51 : 32|8@1+ (1,0) [0|255] ""  PC,MBMU
 SG_ S2A_SUMDATA3_CUS_Reserve6_51 : 40|8@1+ (1,0) [0|255] ""  PC,MBMU
 SG_ S2A_SUMDATA3_CUS_Reserve7_51 : 48|8@1+ (1,0) [0|255] ""  PC,MBMU
 SG_ S2A_SUMDATA3_CUS_Reserve8_51 : 56|8@1+ (1,0) [0|255] ""  PC,MBMU

BO_ 2339635060 S2A_SUMDATA3_CUS__52: 8 SBMU
 SG_ S2A_SUMDATA3_CUS_Reserve1_52 : 0|8@1+ (1,0) [0|255] ""  PC,MBMU
 SG_ S2A_SUMDATA3_CUS_Reserve2_52 : 8|8@1+ (1,0) [0|255] ""  PC,MBMU
 SG_ S2A_SUMDATA3_CUS_Reserve3_52 : 16|8@1+ (1,0) [0|255] ""  PC,MBMU
 SG_ S2A_SUMDATA3_CUS_Reserve4_52 : 24|8@1+ (1,0) [0|255] ""  PC,MBMU
 SG_ S2A_SUMDATA3_CUS_Reserve5_52 : 32|8@1+ (1,0) [0|255] ""  PC,MBMU
 SG_ S2A_SUMDATA3_CUS_Reserve6_52 : 40|8@1+ (1,0) [0|255] ""  PC,MBMU
 SG_ S2A_SUMDATA3_CUS_Reserve7_52 : 48|8@1+ (1,0) [0|255] ""  PC,MBMU
 SG_ S2A_SUMDATA3_CUS_Reserve8_52 : 56|8@1+ (1,0) [0|255] ""  PC,MBMU

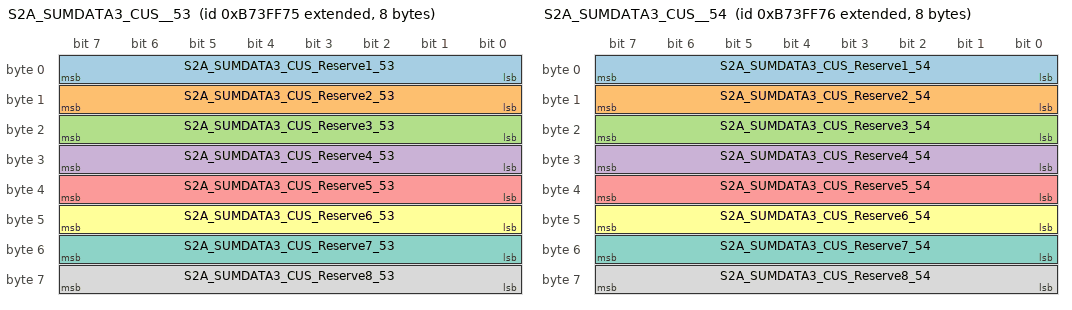
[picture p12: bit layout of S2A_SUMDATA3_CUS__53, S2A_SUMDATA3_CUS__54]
BO_ 2339635061 S2A_SUMDATA3_CUS__53: 8 SBMU
 SG_ S2A_SUMDATA3_CUS_Reserve1_53 : 0|8@1+ (1,0) [0|255] ""  PC,MBMU
 SG_ S2A_SUMDATA3_CUS_Reserve2_53 : 8|8@1+ (1,0) [0|255] ""  PC,MBMU
 SG_ S2A_SUMDATA3_CUS_Reserve3_53 : 16|8@1+ (1,0) [0|255] ""  PC,MBMU
 SG_ S2A_SUMDATA3_CUS_Reserve4_53 : 24|8@1+ (1,0) [0|255] ""  PC,MBMU
 SG_ S2A_SUMDATA3_CUS_Reserve5_53 : 32|8@1+ (1,0) [0|255] ""  PC,MBMU
 SG_ S2A_SUMDATA3_CUS_Reserve6_53 : 40|8@1+ (1,0) [0|255] ""  PC,MBMU
 SG_ S2A_SUMDATA3_CUS_Reserve7_53 : 48|8@1+ (1,0) [0|255] ""  PC,MBMU
 SG_ S2A_SUMDATA3_CUS_Reserve8_53 : 56|8@1+ (1,0) [0|255] ""  PC,MBMU

BO_ 2339635062 S2A_SUMDATA3_CUS__54: 8 SBMU
 SG_ S2A_SUMDATA3_CUS_Reserve1_54 : 0|8@1+ (1,0) [0|255] ""  PC,MBMU
 SG_ S2A_SUMDATA3_CUS_Reserve2_54 : 8|8@1+ (1,0) [0|255] ""  PC,MBMU
 SG_ S2A_SUMDATA3_CUS_Reserve3_54 : 16|8@1+ (1,0) [0|255] ""  PC,MBMU
 SG_ S2A_SUMDATA3_CUS_Reserve4_54 : 24|8@1+ (1,0) [0|255] ""  PC,MBMU
 SG_ S2A_SUMDATA3_CUS_Reserve5_54 : 32|8@1+ (1,0) [0|255] ""  PC,MBMU
 SG_ S2A_SUMDATA3_CUS_Reserve6_54 : 40|8@1+ (1,0) [0|255] ""  PC,MBMU
 SG_ S2A_SUMDATA3_CUS_Reserve7_54 : 48|8@1+ (1,0) [0|255] ""  PC,MBMU
 SG_ S2A_SUMDATA3_CUS_Reserve8_54 : 56|8@1+ (1,0) [0|255] ""  PC,MBMU

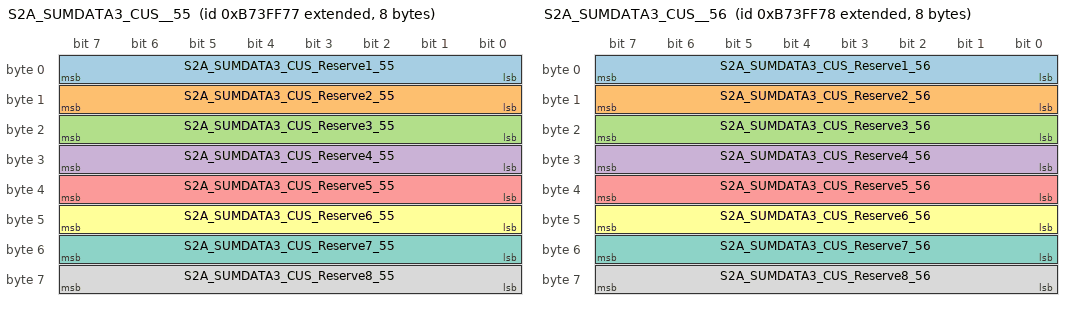
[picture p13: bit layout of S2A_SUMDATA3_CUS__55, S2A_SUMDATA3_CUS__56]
BO_ 2339635063 S2A_SUMDATA3_CUS__55: 8 SBMU
 SG_ S2A_SUMDATA3_CUS_Reserve1_55 : 0|8@1+ (1,0) [0|255] ""  PC,MBMU
 SG_ S2A_SUMDATA3_CUS_Reserve2_55 : 8|8@1+ (1,0) [0|255] ""  PC,MBMU
 SG_ S2A_SUMDATA3_CUS_Reserve3_55 : 16|8@1+ (1,0) [0|255] ""  PC,MBMU
 SG_ S2A_SUMDATA3_CUS_Reserve4_55 : 24|8@1+ (1,0) [0|255] ""  PC,MBMU
 SG_ S2A_SUMDATA3_CUS_Reserve5_55 : 32|8@1+ (1,0) [0|255] ""  PC,MBMU
 SG_ S2A_SUMDATA3_CUS_Reserve6_55 : 40|8@1+ (1,0) [0|255] ""  PC,MBMU
 SG_ S2A_SUMDATA3_CUS_Reserve7_55 : 48|8@1+ (1,0) [0|255] ""  PC,MBMU
 SG_ S2A_SUMDATA3_CUS_Reserve8_55 : 56|8@1+ (1,0) [0|255] ""  PC,MBMU

BO_ 2339635064 S2A_SUMDATA3_CUS__56: 8 SBMU
 SG_ S2A_SUMDATA3_CUS_Reserve1_56 : 0|8@1+ (1,0) [0|255] ""  PC,MBMU
 SG_ S2A_SUMDATA3_CUS_Reserve2_56 : 8|8@1+ (1,0) [0|255] ""  PC,MBMU
 SG_ S2A_SUMDATA3_CUS_Reserve3_56 : 16|8@1+ (1,0) [0|255] ""  PC,MBMU
 SG_ S2A_SUMDATA3_CUS_Reserve4_56 : 24|8@1+ (1,0) [0|255] ""  PC,MBMU
 SG_ S2A_SUMDATA3_CUS_Reserve5_56 : 32|8@1+ (1,0) [0|255] ""  PC,MBMU
 SG_ S2A_SUMDATA3_CUS_Reserve6_56 : 40|8@1+ (1,0) [0|255] ""  PC,MBMU
 SG_ S2A_SUMDATA3_CUS_Reserve7_56 : 48|8@1+ (1,0) [0|255] ""  PC,MBMU
 SG_ S2A_SUMDATA3_CUS_Reserve8_56 : 56|8@1+ (1,0) [0|255] ""  PC,MBMU

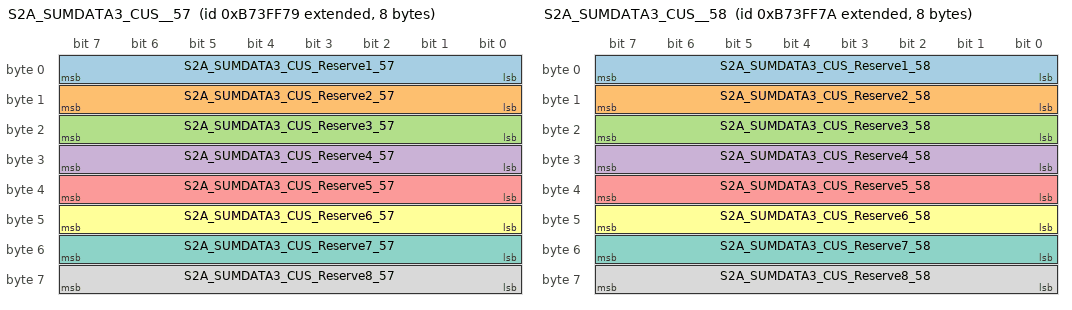
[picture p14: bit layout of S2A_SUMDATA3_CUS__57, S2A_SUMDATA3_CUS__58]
BO_ 2339635065 S2A_SUMDATA3_CUS__57: 8 SBMU
 SG_ S2A_SUMDATA3_CUS_Reserve1_57 : 0|8@1+ (1,0) [0|255] ""  PC,MBMU
 SG_ S2A_SUMDATA3_CUS_Reserve2_57 : 8|8@1+ (1,0) [0|255] ""  PC,MBMU
 SG_ S2A_SUMDATA3_CUS_Reserve3_57 : 16|8@1+ (1,0) [0|255] ""  PC,MBMU
 SG_ S2A_SUMDATA3_CUS_Reserve4_57 : 24|8@1+ (1,0) [0|255] ""  PC,MBMU
 SG_ S2A_SUMDATA3_CUS_Reserve5_57 : 32|8@1+ (1,0) [0|255] ""  PC,MBMU
 SG_ S2A_SUMDATA3_CUS_Reserve6_57 : 40|8@1+ (1,0) [0|255] ""  PC,MBMU
 SG_ S2A_SUMDATA3_CUS_Reserve7_57 : 48|8@1+ (1,0) [0|255] ""  PC,MBMU
 SG_ S2A_SUMDATA3_CUS_Reserve8_57 : 56|8@1+ (1,0) [0|255] ""  PC,MBMU

BO_ 2339635066 S2A_SUMDATA3_CUS__58: 8 SBMU
 SG_ S2A_SUMDATA3_CUS_Reserve1_58 : 0|8@1+ (1,0) [0|255] ""  PC,MBMU
 SG_ S2A_SUMDATA3_CUS_Reserve2_58 : 8|8@1+ (1,0) [0|255] ""  PC,MBMU
 SG_ S2A_SUMDATA3_CUS_Reserve3_58 : 16|8@1+ (1,0) [0|255] ""  PC,MBMU
 SG_ S2A_SUMDATA3_CUS_Reserve4_58 : 24|8@1+ (1,0) [0|255] ""  PC,MBMU
 SG_ S2A_SUMDATA3_CUS_Reserve5_58 : 32|8@1+ (1,0) [0|255] ""  PC,MBMU
 SG_ S2A_SUMDATA3_CUS_Reserve6_58 : 40|8@1+ (1,0) [0|255] ""  PC,MBMU
 SG_ S2A_SUMDATA3_CUS_Reserve7_58 : 48|8@1+ (1,0) [0|255] ""  PC,MBMU
 SG_ S2A_SUMDATA3_CUS_Reserve8_58 : 56|8@1+ (1,0) [0|255] ""  PC,MBMU

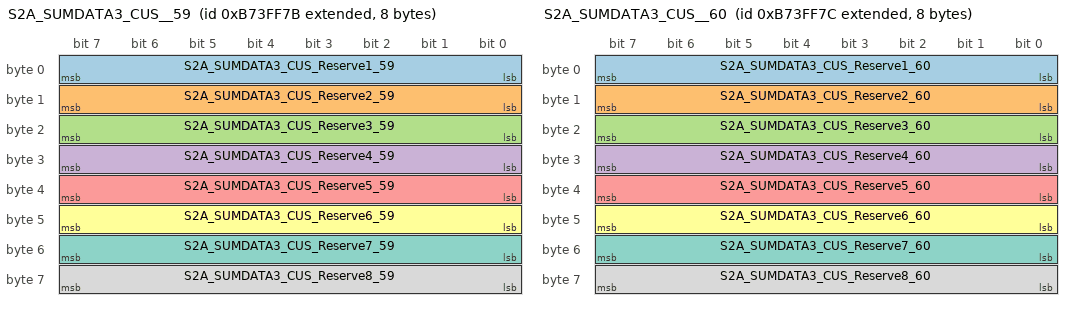
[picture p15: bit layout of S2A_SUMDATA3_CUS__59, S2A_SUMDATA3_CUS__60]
BO_ 2339635067 S2A_SUMDATA3_CUS__59: 8 SBMU
 SG_ S2A_SUMDATA3_CUS_Reserve1_59 : 0|8@1+ (1,0) [0|255] ""  PC,MBMU
 SG_ S2A_SUMDATA3_CUS_Reserve2_59 : 8|8@1+ (1,0) [0|255] ""  PC,MBMU
 SG_ S2A_SUMDATA3_CUS_Reserve3_59 : 16|8@1+ (1,0) [0|255] ""  PC,MBMU
 SG_ S2A_SUMDATA3_CUS_Reserve4_59 : 24|8@1+ (1,0) [0|255] ""  PC,MBMU
 SG_ S2A_SUMDATA3_CUS_Reserve5_59 : 32|8@1+ (1,0) [0|255] ""  PC,MBMU
 SG_ S2A_SUMDATA3_CUS_Reserve6_59 : 40|8@1+ (1,0) [0|255] ""  PC,MBMU
 SG_ S2A_SUMDATA3_CUS_Reserve7_59 : 48|8@1+ (1,0) [0|255] ""  PC,MBMU
 SG_ S2A_SUMDATA3_CUS_Reserve8_59 : 56|8@1+ (1,0) [0|255] ""  PC,MBMU

BO_ 2339635068 S2A_SUMDATA3_CUS__60: 8 SBMU
 SG_ S2A_SUMDATA3_CUS_Reserve1_60 : 0|8@1+ (1,0) [0|255] ""  PC,MBMU
 SG_ S2A_SUMDATA3_CUS_Reserve2_60 : 8|8@1+ (1,0) [0|255] ""  PC,MBMU
 SG_ S2A_SUMDATA3_CUS_Reserve3_60 : 16|8@1+ (1,0) [0|255] ""  PC,MBMU
 SG_ S2A_SUMDATA3_CUS_Reserve4_60 : 24|8@1+ (1,0) [0|255] ""  PC,MBMU
 SG_ S2A_SUMDATA3_CUS_Reserve5_60 : 32|8@1+ (1,0) [0|255] ""  PC,MBMU
 SG_ S2A_SUMDATA3_CUS_Reserve6_60 : 40|8@1+ (1,0) [0|255] ""  PC,MBMU
 SG_ S2A_SUMDATA3_CUS_Reserve7_60 : 48|8@1+ (1,0) [0|255] ""  PC,MBMU
 SG_ S2A_SUMDATA3_CUS_Reserve8_60 : 56|8@1+ (1,0) [0|255] ""  PC,MBMU

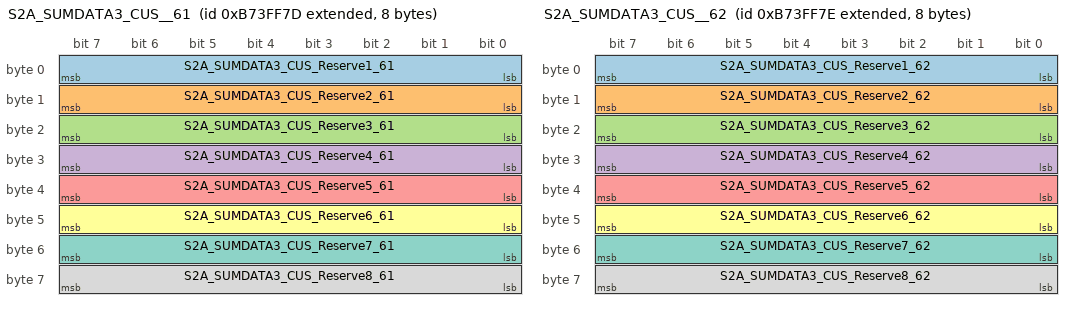
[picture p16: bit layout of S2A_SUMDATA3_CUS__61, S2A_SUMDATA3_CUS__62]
BO_ 2339635069 S2A_SUMDATA3_CUS__61: 8 SBMU
 SG_ S2A_SUMDATA3_CUS_Reserve1_61 : 0|8@1+ (1,0) [0|255] ""  PC,MBMU
 SG_ S2A_SUMDATA3_CUS_Reserve2_61 : 8|8@1+ (1,0) [0|255] ""  PC,MBMU
 SG_ S2A_SUMDATA3_CUS_Reserve3_61 : 16|8@1+ (1,0) [0|255] ""  PC,MBMU
 SG_ S2A_SUMDATA3_CUS_Reserve4_61 : 24|8@1+ (1,0) [0|255] ""  PC,MBMU
 SG_ S2A_SUMDATA3_CUS_Reserve5_61 : 32|8@1+ (1,0) [0|255] ""  PC,MBMU
 SG_ S2A_SUMDATA3_CUS_Reserve6_61 : 40|8@1+ (1,0) [0|255] ""  PC,MBMU
 SG_ S2A_SUMDATA3_CUS_Reserve7_61 : 48|8@1+ (1,0) [0|255] ""  PC,MBMU
 SG_ S2A_SUMDATA3_CUS_Reserve8_61 : 56|8@1+ (1,0) [0|255] ""  PC,MBMU

BO_ 2339635070 S2A_SUMDATA3_CUS__62: 8 SBMU
 SG_ S2A_SUMDATA3_CUS_Reserve1_62 : 0|8@1+ (1,0) [0|255] ""  PC,MBMU
 SG_ S2A_SUMDATA3_CUS_Reserve2_62 : 8|8@1+ (1,0) [0|255] ""  PC,MBMU
 SG_ S2A_SUMDATA3_CUS_Reserve3_62 : 16|8@1+ (1,0) [0|255] ""  PC,MBMU
 SG_ S2A_SUMDATA3_CUS_Reserve4_62 : 24|8@1+ (1,0) [0|255] ""  PC,MBMU
 SG_ S2A_SUMDATA3_CUS_Reserve5_62 : 32|8@1+ (1,0) [0|255] ""  PC,MBMU
 SG_ S2A_SUMDATA3_CUS_Reserve6_62 : 40|8@1+ (1,0) [0|255] ""  PC,MBMU
 SG_ S2A_SUMDATA3_CUS_Reserve7_62 : 48|8@1+ (1,0) [0|255] ""  PC,MBMU
 SG_ S2A_SUMDATA3_CUS_Reserve8_62 : 56|8@1+ (1,0) [0|255] ""  PC,MBMU

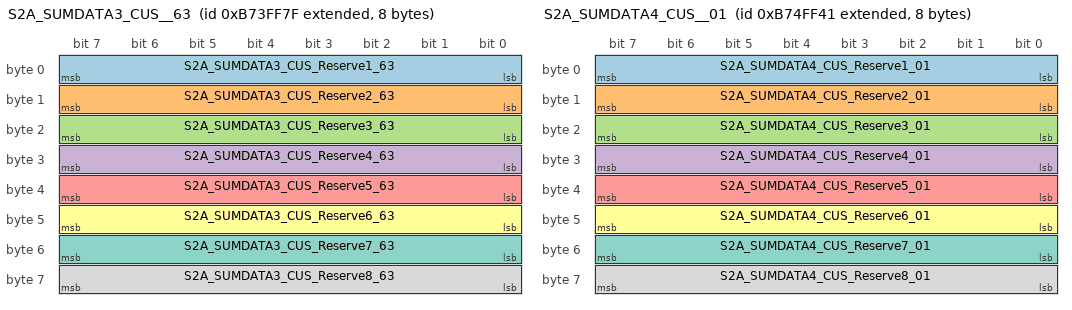
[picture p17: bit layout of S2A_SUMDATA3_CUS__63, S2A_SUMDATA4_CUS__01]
BO_ 2339635071 S2A_SUMDATA3_CUS__63: 8 SBMU
 SG_ S2A_SUMDATA3_CUS_Reserve1_63 : 0|8@1+ (1,0) [0|255] ""  PC,MBMU
 SG_ S2A_SUMDATA3_CUS_Reserve2_63 : 8|8@1+ (1,0) [0|255] ""  PC,MBMU
 SG_ S2A_SUMDATA3_CUS_Reserve3_63 : 16|8@1+ (1,0) [0|255] ""  PC,MBMU
 SG_ S2A_SUMDATA3_CUS_Reserve4_63 : 24|8@1+ (1,0) [0|255] ""  PC,MBMU
 SG_ S2A_SUMDATA3_CUS_Reserve5_63 : 32|8@1+ (1,0) [0|255] ""  PC,MBMU
 SG_ S2A_SUMDATA3_CUS_Reserve6_63 : 40|8@1+ (1,0) [0|255] ""  PC,MBMU
 SG_ S2A_SUMDATA3_CUS_Reserve7_63 : 48|8@1+ (1,0) [0|255] ""  PC,MBMU
 SG_ S2A_SUMDATA3_CUS_Reserve8_63 : 56|8@1+ (1,0) [0|255] ""  PC,MBMU

BO_ 2339700545 S2A_SUMDATA4_CUS__01: 8 SBMU
 SG_ S2A_SUMDATA4_CUS_Reserve1_01 : 0|8@1+ (1,0) [0|255] ""  PC,MBMU
 SG_ S2A_SUMDATA4_CUS_Reserve2_01 : 8|8@1+ (1,0) [0|255] ""  PC,MBMU
 SG_ S2A_SUMDATA4_CUS_Reserve3_01 : 16|8@1+ (1,0) [0|255] ""  PC,MBMU
 SG_ S2A_SUMDATA4_CUS_Reserve4_01 : 24|8@1+ (1,0) [0|255] ""  PC,MBMU
 SG_ S2A_SUMDATA4_CUS_Reserve5_01 : 32|8@1+ (1,0) [0|255] ""  PC,MBMU
 SG_ S2A_SUMDATA4_CUS_Reserve6_01 : 40|8@1+ (1,0) [0|255] ""  PC,MBMU
 SG_ S2A_SUMDATA4_CUS_Reserve7_01 : 48|8@1+ (1,0) [0|255] ""  PC,MBMU
 SG_ S2A_SUMDATA4_CUS_Reserve8_01 : 56|8@1+ (1,0) [0|255] ""  PC,MBMU

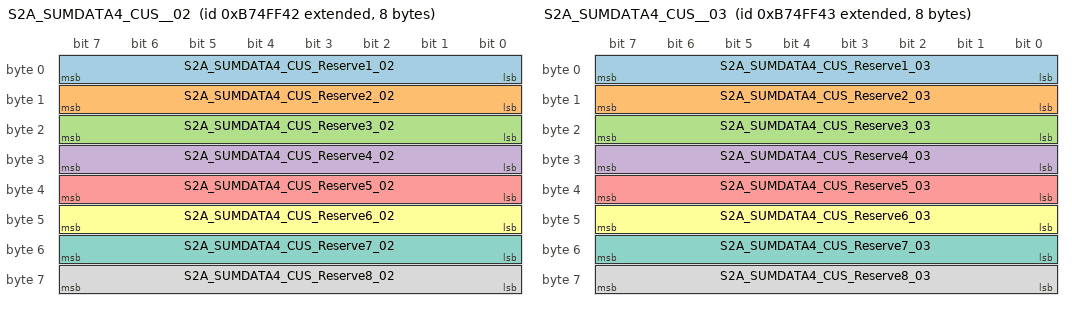
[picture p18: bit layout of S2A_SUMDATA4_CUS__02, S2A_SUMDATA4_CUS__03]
BO_ 2339700546 S2A_SUMDATA4_CUS__02: 8 SBMU
 SG_ S2A_SUMDATA4_CUS_Reserve1_02 : 0|8@1+ (1,0) [0|255] ""  PC,MBMU
 SG_ S2A_SUMDATA4_CUS_Reserve2_02 : 8|8@1+ (1,0) [0|255] ""  PC,MBMU
 SG_ S2A_SUMDATA4_CUS_Reserve3_02 : 16|8@1+ (1,0) [0|255] ""  PC,MBMU
 SG_ S2A_SUMDATA4_CUS_Reserve4_02 : 24|8@1+ (1,0) [0|255] ""  PC,MBMU
 SG_ S2A_SUMDATA4_CUS_Reserve5_02 : 32|8@1+ (1,0) [0|255] ""  PC,MBMU
 SG_ S2A_SUMDATA4_CUS_Reserve6_02 : 40|8@1+ (1,0) [0|255] ""  PC,MBMU
 SG_ S2A_SUMDATA4_CUS_Reserve7_02 : 48|8@1+ (1,0) [0|255] ""  PC,MBMU
 SG_ S2A_SUMDATA4_CUS_Reserve8_02 : 56|8@1+ (1,0) [0|255] ""  PC,MBMU

BO_ 2339700547 S2A_SUMDATA4_CUS__03: 8 SBMU
 SG_ S2A_SUMDATA4_CUS_Reserve1_03 : 0|8@1+ (1,0) [0|255] ""  PC,MBMU
 SG_ S2A_SUMDATA4_CUS_Reserve2_03 : 8|8@1+ (1,0) [0|255] ""  PC,MBMU
 SG_ S2A_SUMDATA4_CUS_Reserve3_03 : 16|8@1+ (1,0) [0|255] ""  PC,MBMU
 SG_ S2A_SUMDATA4_CUS_Reserve4_03 : 24|8@1+ (1,0) [0|255] ""  PC,MBMU
 SG_ S2A_SUMDATA4_CUS_Reserve5_03 : 32|8@1+ (1,0) [0|255] ""  PC,MBMU
 SG_ S2A_SUMDATA4_CUS_Reserve6_03 : 40|8@1+ (1,0) [0|255] ""  PC,MBMU
 SG_ S2A_SUMDATA4_CUS_Reserve7_03 : 48|8@1+ (1,0) [0|255] ""  PC,MBMU
 SG_ S2A_SUMDATA4_CUS_Reserve8_03 : 56|8@1+ (1,0) [0|255] ""  PC,MBMU

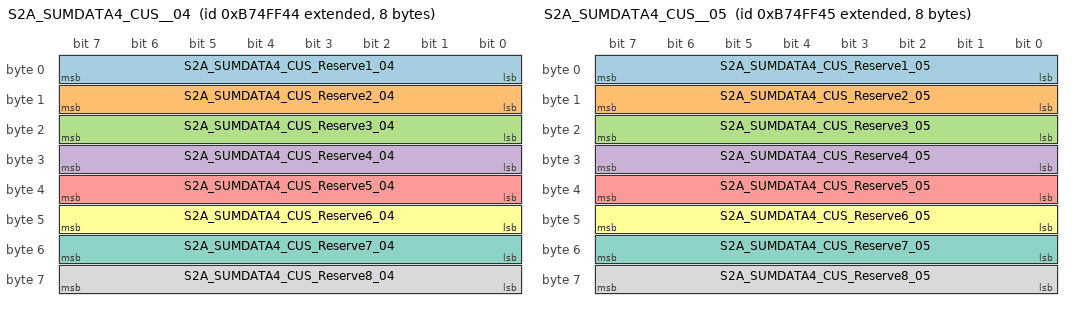
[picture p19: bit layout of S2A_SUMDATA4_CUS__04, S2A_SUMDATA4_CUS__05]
BO_ 2339700548 S2A_SUMDATA4_CUS__04: 8 SBMU
 SG_ S2A_SUMDATA4_CUS_Reserve1_04 : 0|8@1+ (1,0) [0|255] ""  PC,MBMU
 SG_ S2A_SUMDATA4_CUS_Reserve2_04 : 8|8@1+ (1,0) [0|255] ""  PC,MBMU
 SG_ S2A_SUMDATA4_CUS_Reserve3_04 : 16|8@1+ (1,0) [0|255] ""  PC,MBMU
 SG_ S2A_SUMDATA4_CUS_Reserve4_04 : 24|8@1+ (1,0) [0|255] ""  PC,MBMU
 SG_ S2A_SUMDATA4_CUS_Reserve5_04 : 32|8@1+ (1,0) [0|255] ""  PC,MBMU
 SG_ S2A_SUMDATA4_CUS_Reserve6_04 : 40|8@1+ (1,0) [0|255] ""  PC,MBMU
 SG_ S2A_SUMDATA4_CUS_Reserve7_04 : 48|8@1+ (1,0) [0|255] ""  PC,MBMU
 SG_ S2A_SUMDATA4_CUS_Reserve8_04 : 56|8@1+ (1,0) [0|255] ""  PC,MBMU

BO_ 2339700549 S2A_SUMDATA4_CUS__05: 8 SBMU
 SG_ S2A_SUMDATA4_CUS_Reserve1_05 : 0|8@1+ (1,0) [0|255] ""  PC,MBMU
 SG_ S2A_SUMDATA4_CUS_Reserve2_05 : 8|8@1+ (1,0) [0|255] ""  PC,MBMU
 SG_ S2A_SUMDATA4_CUS_Reserve3_05 : 16|8@1+ (1,0) [0|255] ""  PC,MBMU
 SG_ S2A_SUMDATA4_CUS_Reserve4_05 : 24|8@1+ (1,0) [0|255] ""  PC,MBMU
 SG_ S2A_SUMDATA4_CUS_Reserve5_05 : 32|8@1+ (1,0) [0|255] ""  PC,MBMU
 SG_ S2A_SUMDATA4_CUS_Reserve6_05 : 40|8@1+ (1,0) [0|255] ""  PC,MBMU
 SG_ S2A_SUMDATA4_CUS_Reserve7_05 : 48|8@1+ (1,0) [0|255] ""  PC,MBMU
 SG_ S2A_SUMDATA4_CUS_Reserve8_05 : 56|8@1+ (1,0) [0|255] ""  PC,MBMU

BO_ 2339700550 S2A_SUMDATA4_CUS__06: 8 SBMU
 SG_ S2A_SUMDATA4_CUS_Reserve1_06 : 0|8@1+ (1,0) [0|255] ""  PC,MBMU
 SG_ S2A_SUMDATA4_CUS_Reserve2_06 : 8|8@1+ (1,0) [0|255] ""  PC,MBMU
 SG_ S2A_SUMDATA4_CUS_Reserve3_06 : 16|8@1+ (1,0) [0|255] ""  PC,MBMU
 SG_ S2A_SUMDATA4_CUS_Reserve4_06 : 24|8@1+ (1,0) [0|255] ""  PC,MBMU
 SG_ S2A_SUMDATA4_CUS_Reserve5_06 : 32|8@1+ (1,0) [0|255] ""  PC,MBMU
 SG_ S2A_SUMDATA4_CUS_Reserve6_06 : 40|8@1+ (1,0) [0|255] ""  PC,MBMU
 SG_ S2A_SUMDATA4_CUS_Reserve7_06 : 48|8@1+ (1,0) [0|255] ""  PC,MBMU
 SG_ S2A_SUMDATA4_CUS_Reserve8_06 : 56|8@1+ (1,0) [0|255] ""  PC,MBMU

BO_ 2339700551 S2A_SUMDATA4_CUS__07: 8 SBMU
 SG_ S2A_SUMDATA4_CUS_Reserve1_07 : 0|8@1+ (1,0) [0|255] ""  PC,MBMU
 SG_ S2A_SUMDATA4_CUS_Reserve2_07 : 8|8@1+ (1,0) [0|255] ""  PC,MBMU
 SG_ S2A_SUMDATA4_CUS_Reserve3_07 : 16|8@1+ (1,0) [0|255] ""  PC,MBMU
 SG_ S2A_SUMDATA4_CUS_Reserve4_07 : 24|8@1+ (1,0) [0|255] ""  PC,MBMU
 SG_ S2A_SUMDATA4_CUS_Reserve5_07 : 32|8@1+ (1,0) [0|255] ""  PC,MBMU
 SG_ S2A_SUMDATA4_CUS_Reserve6_07 : 40|8@1+ (1,0) [0|255] ""  PC,MBMU
 SG_ S2A_SUMDATA4_CUS_Reserve7_07 : 48|8@1+ (1,0) [0|255] ""  PC,MBMU
 SG_ S2A_SUMDATA4_CUS_Reserve8_07 : 56|8@1+ (1,0) [0|255] ""  PC,MBMU

BO_ 2339700552 S2A_SUMDATA4_CUS__08: 8 SBMU
 SG_ S2A_SUMDATA4_CUS_Reserve1_08 : 0|8@1+ (1,0) [0|255] ""  PC,MBMU
 SG_ S2A_SUMDATA4_CUS_Reserve2_08 : 8|8@1+ (1,0) [0|255] ""  PC,MBMU
 SG_ S2A_SUMDATA4_CUS_Reserve3_08 : 16|8@1+ (1,0) [0|255] ""  PC,MBMU
 SG_ S2A_SUMDATA4_CUS_Reserve4_08 : 24|8@1+ (1,0) [0|255] ""  PC,MBMU
 SG_ S2A_SUMDATA4_CUS_Reserve5_08 : 32|8@1+ (1,0) [0|255] ""  PC,MBMU
 SG_ S2A_SUMDATA4_CUS_Reserve6_08 : 40|8@1+ (1,0) [0|255] ""  PC,MBMU
 SG_ S2A_SUMDATA4_CUS_Reserve7_08 : 48|8@1+ (1,0) [0|255] ""  PC,MBMU
 SG_ S2A_SUMDATA4_CUS_Reserve8_08 : 56|8@1+ (1,0) [0|255] ""  PC,MBMU

BO_ 2339700553 S2A_SUMDATA4_CUS__09: 8 SBMU
 SG_ S2A_SUMDATA4_CUS_Reserve1_09 : 0|8@1+ (1,0) [0|255] ""  PC,MBMU
 SG_ S2A_SUMDATA4_CUS_Reserve2_09 : 8|8@1+ (1,0) [0|255] ""  PC,MBMU
 SG_ S2A_SUMDATA4_CUS_Reserve3_09 : 16|8@1+ (1,0) [0|255] ""  PC,MBMU
 SG_ S2A_SUMDATA4_CUS_Reserve4_09 : 24|8@1+ (1,0) [0|255] ""  PC,MBMU
 SG_ S2A_SUMDATA4_CUS_Reserve5_09 : 32|8@1+ (1,0) [0|255] ""  PC,MBMU
 SG_ S2A_SUMDATA4_CUS_Reserve6_09 : 40|8@1+ (1,0) [0|255] ""  PC,MBMU
 SG_ S2A_SUMDATA4_CUS_Reserve7_09 : 48|8@1+ (1,0) [0|255] ""  PC,MBMU
 SG_ S2A_SUMDATA4_CUS_Reserve8_09 : 56|8@1+ (1,0) [0|255] ""  PC,MBMU

BO_ 2339700554 S2A_SUMDATA4_CUS__10: 8 SBMU
 SG_ S2A_SUMDATA4_CUS_Reserve1_10 : 0|8@1+ (1,0) [0|255] ""  PC,MBMU
 SG_ S2A_SUMDATA4_CUS_Reserve2_10 : 8|8@1+ (1,0) [0|255] ""  PC,MBMU
 SG_ S2A_SUMDATA4_CUS_Reserve3_10 : 16|8@1+ (1,0) [0|255] ""  PC,MBMU
 SG_ S2A_SUMDATA4_CUS_Reserve4_10 : 24|8@1+ (1,0) [0|255] ""  PC,MBMU
 SG_ S2A_SUMDATA4_CUS_Reserve5_10 : 32|8@1+ (1,0) [0|255] ""  PC,MBMU
 SG_ S2A_SUMDATA4_CUS_Reserve6_10 : 40|8@1+ (1,0) [0|255] ""  PC,MBMU
 SG_ S2A_SUMDATA4_CUS_Reserve7_10 : 48|8@1+ (1,0) [0|255] ""  PC,MBMU
 SG_ S2A_SUMDATA4_CUS_Reserve8_10 : 56|8@1+ (1,0) [0|255] ""  PC,MBMU

BO_ 2339700555 S2A_SUMDATA4_CUS__11: 8 SBMU
 SG_ S2A_SUMDATA4_CUS_Reserve1_11 : 0|8@1+ (1,0) [0|255] ""  PC,MBMU
 SG_ S2A_SUMDATA4_CUS_Reserve2_11 : 8|8@1+ (1,0) [0|255] ""  PC,MBMU
 SG_ S2A_SUMDATA4_CUS_Reserve3_11 : 16|8@1+ (1,0) [0|255] ""  PC,MBMU
 SG_ S2A_SUMDATA4_CUS_Reserve4_11 : 24|8@1+ (1,0) [0|255] ""  PC,MBMU
 SG_ S2A_SUMDATA4_CUS_Reserve5_11 : 32|8@1+ (1,0) [0|255] ""  PC,MBMU
 SG_ S2A_SUMDATA4_CUS_Reserve6_11 : 40|8@1+ (1,0) [0|255] ""  PC,MBMU
 SG_ S2A_SUMDATA4_CUS_Reserve7_11 : 48|8@1+ (1,0) [0|255] ""  PC,MBMU
 SG_ S2A_SUMDATA4_CUS_Reserve8_11 : 56|8@1+ (1,0) [0|255] ""  PC,MBMU

BO_ 2339700556 S2A_SUMDATA4_CUS__12: 8 SBMU
 SG_ S2A_SUMDATA4_CUS_Reserve1_12 : 0|8@1+ (1,0) [0|255] ""  PC,MBMU
 SG_ S2A_SUMDATA4_CUS_Reserve2_12 : 8|8@1+ (1,0) [0|255] ""  PC,MBMU
 SG_ S2A_SUMDATA4_CUS_Reserve3_12 : 16|8@1+ (1,0) [0|255] ""  PC,MBMU
 SG_ S2A_SUMDATA4_CUS_Reserve4_12 : 24|8@1+ (1,0) [0|255] ""  PC,MBMU
 SG_ S2A_SUMDATA4_CUS_Reserve5_12 : 32|8@1+ (1,0) [0|255] ""  PC,MBMU
 SG_ S2A_SUMDATA4_CUS_Reserve6_12 : 40|8@1+ (1,0) [0|255] ""  PC,MBMU
 SG_ S2A_SUMDATA4_CUS_Reserve7_12 : 48|8@1+ (1,0) [0|255] ""  PC,MBMU
 SG_ S2A_SUMDATA4_CUS_Reserve8_12 : 56|8@1+ (1,0) [0|255] ""  PC,MBMU

BO_ 2339700557 S2A_SUMDATA4_CUS__13: 8 SBMU
 SG_ S2A_SUMDATA4_CUS_Reserve1_13 : 0|8@1+ (1,0) [0|255] ""  PC,MBMU
 SG_ S2A_SUMDATA4_CUS_Reserve2_13 : 8|8@1+ (1,0) [0|255] ""  PC,MBMU
 SG_ S2A_SUMDATA4_CUS_Reserve3_13 : 16|8@1+ (1,0) [0|255] ""  PC,MBMU
 SG_ S2A_SUMDATA4_CUS_Reserve4_13 : 24|8@1+ (1,0) [0|255] ""  PC,MBMU
 SG_ S2A_SUMDATA4_CUS_Reserve5_13 : 32|8@1+ (1,0) [0|255] ""  PC,MBMU
 SG_ S2A_SUMDATA4_CUS_Reserve6_13 : 40|8@1+ (1,0) [0|255] ""  PC,MBMU
 SG_ S2A_SUMDATA4_CUS_Reserve7_13 : 48|8@1+ (1,0) [0|255] ""  PC,MBMU
 SG_ S2A_SUMDATA4_CUS_Reserve8_13 : 56|8@1+ (1,0) [0|255] ""  PC,MBMU

BO_ 2339700558 S2A_SUMDATA4_CUS__14: 8 SBMU
 SG_ S2A_SUMDATA4_CUS_Reserve1_14 : 0|8@1+ (1,0) [0|255] ""  PC,MBMU
 SG_ S2A_SUMDATA4_CUS_Reserve2_14 : 8|8@1+ (1,0) [0|255] ""  PC,MBMU
 SG_ S2A_SUMDATA4_CUS_Reserve3_14 : 16|8@1+ (1,0) [0|255] ""  PC,MBMU
 SG_ S2A_SUMDATA4_CUS_Reserve4_14 : 24|8@1+ (1,0) [0|255] ""  PC,MBMU
 SG_ S2A_SUMDATA4_CUS_Reserve5_14 : 32|8@1+ (1,0) [0|255] ""  PC,MBMU
 SG_ S2A_SUMDATA4_CUS_Reserve6_14 : 40|8@1+ (1,0) [0|255] ""  PC,MBMU
 SG_ S2A_SUMDATA4_CUS_Reserve7_14 : 48|8@1+ (1,0) [0|255] ""  PC,MBMU
 SG_ S2A_SUMDATA4_CUS_Reserve8_14 : 56|8@1+ (1,0) [0|255] ""  PC,MBMU

BO_ 2339700559 S2A_SUMDATA4_CUS__15: 8 SBMU
 SG_ S2A_SUMDATA4_CUS_Reserve1_15 : 0|8@1+ (1,0) [0|255] ""  PC,MBMU
 SG_ S2A_SUMDATA4_CUS_Reserve2_15 : 8|8@1+ (1,0) [0|255] ""  PC,MBMU
 SG_ S2A_SUMDATA4_CUS_Reserve3_15 : 16|8@1+ (1,0) [0|255] ""  PC,MBMU
 SG_ S2A_SUMDATA4_CUS_Reserve4_15 : 24|8@1+ (1,0) [0|255] ""  PC,MBMU
 SG_ S2A_SUMDATA4_CUS_Reserve5_15 : 32|8@1+ (1,0) [0|255] ""  PC,MBMU
 SG_ S2A_SUMDATA4_CUS_Reserve6_15 : 40|8@1+ (1,0) [0|255] ""  PC,MBMU
 SG_ S2A_SUMDATA4_CUS_Reserve7_15 : 48|8@1+ (1,0) [0|255] ""  PC,MBMU
 SG_ S2A_SUMDATA4_CUS_Reserve8_15 : 56|8@1+ (1,0) [0|255] ""  PC,MBMU

BO_ 2339700560 S2A_SUMDATA4_CUS__16: 8 SBMU
 SG_ S2A_SUMDATA4_CUS_Reserve1_16 : 0|8@1+ (1,0) [0|255] ""  PC,MBMU
 SG_ S2A_SUMDATA4_CUS_Reserve2_16 : 8|8@1+ (1,0) [0|255] ""  PC,MBMU
 SG_ S2A_SUMDATA4_CUS_Reserve3_16 : 16|8@1+ (1,0) [0|255] ""  PC,MBMU
 SG_ S2A_SUMDATA4_CUS_Reserve4_16 : 24|8@1+ (1,0) [0|255] ""  PC,MBMU
 SG_ S2A_SUMDATA4_CUS_Reserve5_16 : 32|8@1+ (1,0) [0|255] ""  PC,MBMU
 SG_ S2A_SUMDATA4_CUS_Reserve6_16 : 40|8@1+ (1,0) [0|255] ""  PC,MBMU
 SG_ S2A_SUMDATA4_CUS_Reserve7_16 : 48|8@1+ (1,0) [0|255] ""  PC,MBMU
 SG_ S2A_SUMDATA4_CUS_Reserve8_16 : 56|8@1+ (1,0) [0|255] ""  PC,MBMU

BO_ 2339700561 S2A_SUMDATA4_CUS__17: 8 SBMU
 SG_ S2A_SUMDATA4_CUS_Reserve1_17 : 0|8@1+ (1,0) [0|255] ""  PC,MBMU
 SG_ S2A_SUMDATA4_CUS_Reserve2_17 : 8|8@1+ (1,0) [0|255] ""  PC,MBMU
 SG_ S2A_SUMDATA4_CUS_Reserve3_17 : 16|8@1+ (1,0) [0|255] ""  PC,MBMU
 SG_ S2A_SUMDATA4_CUS_Reserve4_17 : 24|8@1+ (1,0) [0|255] ""  PC,MBMU
 SG_ S2A_SUMDATA4_CUS_Reserve5_17 : 32|8@1+ (1,0) [0|255] ""  PC,MBMU
 SG_ S2A_SUMDATA4_CUS_Reserve6_17 : 40|8@1+ (1,0) [0|255] ""  PC,MBMU
 SG_ S2A_SUMDATA4_CUS_Reserve7_17 : 48|8@1+ (1,0) [0|255] ""  PC,MBMU
 SG_ S2A_SUMDATA4_CUS_Reserve8_17 : 56|8@1+ (1,0) [0|255] ""  PC,MBMU

BO_ 2339700562 S2A_SUMDATA4_CUS__18: 8 SBMU
 SG_ S2A_SUMDATA4_CUS_Reserve1_18 : 0|8@1+ (1,0) [0|255] ""  PC,MBMU
 SG_ S2A_SUMDATA4_CUS_Reserve2_18 : 8|8@1+ (1,0) [0|255] ""  PC,MBMU
 SG_ S2A_SUMDATA4_CUS_Reserve3_18 : 16|8@1+ (1,0) [0|255] ""  PC,MBMU
 SG_ S2A_SUMDATA4_CUS_Reserve4_18 : 24|8@1+ (1,0) [0|255] ""  PC,MBMU
 SG_ S2A_SUMDATA4_CUS_Reserve5_18 : 32|8@1+ (1,0) [0|255] ""  PC,MBMU
 SG_ S2A_SUMDATA4_CUS_Reserve6_18 : 40|8@1+ (1,0) [0|255] ""  PC,MBMU
 SG_ S2A_SUMDATA4_CUS_Reserve7_18 : 48|8@1+ (1,0) [0|255] ""  PC,MBMU
 SG_ S2A_SUMDATA4_CUS_Reserve8_18 : 56|8@1+ (1,0) [0|255] ""  PC,MBMU

BO_ 2339700563 S2A_SUMDATA4_CUS__19: 8 SBMU
 SG_ S2A_SUMDATA4_CUS_Reserve1_19 : 0|8@1+ (1,0) [0|255] ""  PC,MBMU
 SG_ S2A_SUMDATA4_CUS_Reserve2_19 : 8|8@1+ (1,0) [0|255] ""  PC,MBMU
 SG_ S2A_SUMDATA4_CUS_Reserve3_19 : 16|8@1+ (1,0) [0|255] ""  PC,MBMU
 SG_ S2A_SUMDATA4_CUS_Reserve4_19 : 24|8@1+ (1,0) [0|255] ""  PC,MBMU
 SG_ S2A_SUMDATA4_CUS_Reserve5_19 : 32|8@1+ (1,0) [0|255] ""  PC,MBMU
 SG_ S2A_SUMDATA4_CUS_Reserve6_19 : 40|8@1+ (1,0) [0|255] ""  PC,MBMU
 SG_ S2A_SUMDATA4_CUS_Reserve7_19 : 48|8@1+ (1,0) [0|255] ""  PC,MBMU
 SG_ S2A_SUMDATA4_CUS_Reserve8_19 : 56|8@1+ (1,0) [0|255] ""  PC,MBMU

BO_ 2339700564 S2A_SUMDATA4_CUS__20: 8 SBMU
 SG_ S2A_SUMDATA4_CUS_Reserve1_20 : 0|8@1+ (1,0) [0|255] ""  PC,MBMU
 SG_ S2A_SUMDATA4_CUS_Reserve2_20 : 8|8@1+ (1,0) [0|255] ""  PC,MBMU
 SG_ S2A_SUMDATA4_CUS_Reserve3_20 : 16|8@1+ (1,0) [0|255] ""  PC,MBMU
 SG_ S2A_SUMDATA4_CUS_Reserve4_20 : 24|8@1+ (1,0) [0|255] ""  PC,MBMU
 SG_ S2A_SUMDATA4_CUS_Reserve5_20 : 32|8@1+ (1,0) [0|255] ""  PC,MBMU
 SG_ S2A_SUMDATA4_CUS_Reserve6_20 : 40|8@1+ (1,0) [0|255] ""  PC,MBMU
 SG_ S2A_SUMDATA4_CUS_Reserve7_20 : 48|8@1+ (1,0) [0|255] ""  PC,MBMU
 SG_ S2A_SUMDATA4_CUS_Reserve8_20 : 56|8@1+ (1,0) [0|255] ""  PC,MBMU

BO_ 2339700565 S2A_SUMDATA4_CUS__21: 8 SBMU
 SG_ S2A_SUMDATA4_CUS_Reserve1_21 : 0|8@1+ (1,0) [0|255] ""  PC,MBMU
 SG_ S2A_SUMDATA4_CUS_Reserve2_21 : 8|8@1+ (1,0) [0|255] ""  PC,MBMU
 SG_ S2A_SUMDATA4_CUS_Reserve3_21 : 16|8@1+ (1,0) [0|255] ""  PC,MBMU
 SG_ S2A_SUMDATA4_CUS_Reserve4_21 : 24|8@1+ (1,0) [0|255] ""  PC,MBMU
 SG_ S2A_SUMDATA4_CUS_Reserve5_21 : 32|8@1+ (1,0) [0|255] ""  PC,MBMU
 SG_ S2A_SUMDATA4_CUS_Reserve6_21 : 40|8@1+ (1,0) [0|255] ""  PC,MBMU
 SG_ S2A_SUMDATA4_CUS_Reserve7_21 : 48|8@1+ (1,0) [0|255] ""  PC,MBMU
 SG_ S2A_SUMDATA4_CUS_Reserve8_21 : 56|8@1+ (1,0) [0|255] ""  PC,MBMU

BO_ 2339700566 S2A_SUMDATA4_CUS__22: 8 SBMU
 SG_ S2A_SUMDATA4_CUS_Reserve1_22 : 0|8@1+ (1,0) [0|255] ""  PC,MBMU
 SG_ S2A_SUMDATA4_CUS_Reserve2_22 : 8|8@1+ (1,0) [0|255] ""  PC,MBMU
 SG_ S2A_SUMDATA4_CUS_Reserve3_22 : 16|8@1+ (1,0) [0|255] ""  PC,MBMU
 SG_ S2A_SUMDATA4_CUS_Reserve4_22 : 24|8@1+ (1,0) [0|255] ""  PC,MBMU
 SG_ S2A_SUMDATA4_CUS_Reserve5_22 : 32|8@1+ (1,0) [0|255] ""  PC,MBMU
 SG_ S2A_SUMDATA4_CUS_Reserve6_22 : 40|8@1+ (1,0) [0|255] ""  PC,MBMU
 SG_ S2A_SUMDATA4_CUS_Reserve7_22 : 48|8@1+ (1,0) [0|255] ""  PC,MBMU
 SG_ S2A_SUMDATA4_CUS_Reserve8_22 : 56|8@1+ (1,0) [0|255] ""  PC,MBMU

BO_ 2339700567 S2A_SUMDATA4_CUS__23: 8 SBMU
 SG_ S2A_SUMDATA4_CUS_Reserve1_23 : 0|8@1+ (1,0) [0|255] ""  PC,MBMU
 SG_ S2A_SUMDATA4_CUS_Reserve2_23 : 8|8@1+ (1,0) [0|255] ""  PC,MBMU
 SG_ S2A_SUMDATA4_CUS_Reserve3_23 : 16|8@1+ (1,0) [0|255] ""  PC,MBMU
 SG_ S2A_SUMDATA4_CUS_Reserve4_23 : 24|8@1+ (1,0) [0|255] ""  PC,MBMU
 SG_ S2A_SUMDATA4_CUS_Reserve5_23 : 32|8@1+ (1,0) [0|255] ""  PC,MBMU
 SG_ S2A_SUMDATA4_CUS_Reserve6_23 : 40|8@1+ (1,0) [0|255] ""  PC,MBMU
 SG_ S2A_SUMDATA4_CUS_Reserve7_23 : 48|8@1+ (1,0) [0|255] ""  PC,MBMU
 SG_ S2A_SUMDATA4_CUS_Reserve8_23 : 56|8@1+ (1,0) [0|255] ""  PC,MBMU

BO_ 2339700568 S2A_SUMDATA4_CUS__24: 8 SBMU
 SG_ S2A_SUMDATA4_CUS_Reserve1_24 : 0|8@1+ (1,0) [0|255] ""  PC,MBMU
 SG_ S2A_SUMDATA4_CUS_Reserve2_24 : 8|8@1+ (1,0) [0|255] ""  PC,MBMU
 SG_ S2A_SUMDATA4_CUS_Reserve3_24 : 16|8@1+ (1,0) [0|255] ""  PC,MBMU
 SG_ S2A_SUMDATA4_CUS_Reserve4_24 : 24|8@1+ (1,0) [0|255] ""  PC,MBMU
 SG_ S2A_SUMDATA4_CUS_Reserve5_24 : 32|8@1+ (1,0) [0|255] ""  PC,MBMU
 SG_ S2A_SUMDATA4_CUS_Reserve6_24 : 40|8@1+ (1,0) [0|255] ""  PC,MBMU
 SG_ S2A_SUMDATA4_CUS_Reserve7_24 : 48|8@1+ (1,0) [0|255] ""  PC,MBMU
 SG_ S2A_SUMDATA4_CUS_Reserve8_24 : 56|8@1+ (1,0) [0|255] ""  PC,MBMU

BO_ 2339700569 S2A_SUMDATA4_CUS__25: 8 SBMU
 SG_ S2A_SUMDATA4_CUS_Reserve1_25 : 0|8@1+ (1,0) [0|255] ""  PC,MBMU
 SG_ S2A_SUMDATA4_CUS_Reserve2_25 : 8|8@1+ (1,0) [0|255] ""  PC,MBMU
 SG_ S2A_SUMDATA4_CUS_Reserve3_25 : 16|8@1+ (1,0) [0|255] ""  PC,MBMU
 SG_ S2A_SUMDATA4_CUS_Reserve4_25 : 24|8@1+ (1,0) [0|255] ""  PC,MBMU
 SG_ S2A_SUMDATA4_CUS_Reserve5_25 : 32|8@1+ (1,0) [0|255] ""  PC,MBMU
 SG_ S2A_SUMDATA4_CUS_Reserve6_25 : 40|8@1+ (1,0) [0|255] ""  PC,MBMU
 SG_ S2A_SUMDATA4_CUS_Reserve7_25 : 48|8@1+ (1,0) [0|255] ""  PC,MBMU
 SG_ S2A_SUMDATA4_CUS_Reserve8_25 : 56|8@1+ (1,0) [0|255] ""  PC,MBMU

BO_ 2339700570 S2A_SUMDATA4_CUS__26: 8 SBMU
 SG_ S2A_SUMDATA4_CUS_Reserve1_26 : 0|8@1+ (1,0) [0|255] ""  PC,MBMU
 SG_ S2A_SUMDATA4_CUS_Reserve2_26 : 8|8@1+ (1,0) [0|255] ""  PC,MBMU
 SG_ S2A_SUMDATA4_CUS_Reserve3_26 : 16|8@1+ (1,0) [0|255] ""  PC,MBMU
 SG_ S2A_SUMDATA4_CUS_Reserve4_26 : 24|8@1+ (1,0) [0|255] ""  PC,MBMU
 SG_ S2A_SUMDATA4_CUS_Reserve5_26 : 32|8@1+ (1,0) [0|255] ""  PC,MBMU
 SG_ S2A_SUMDATA4_CUS_Reserve6_26 : 40|8@1+ (1,0) [0|255] ""  PC,MBMU
 SG_ S2A_SUMDATA4_CUS_Reserve7_26 : 48|8@1+ (1,0) [0|255] ""  PC,MBMU
 SG_ S2A_SUMDATA4_CUS_Reserve8_26 : 56|8@1+ (1,0) [0|255] ""  PC,MBMU

BO_ 2339700571 S2A_SUMDATA4_CUS__27: 8 SBMU
 SG_ S2A_SUMDATA4_CUS_Reserve1_27 : 0|8@1+ (1,0) [0|255] ""  PC,MBMU
 SG_ S2A_SUMDATA4_CUS_Reserve2_27 : 8|8@1+ (1,0) [0|255] ""  PC,MBMU
 SG_ S2A_SUMDATA4_CUS_Reserve3_27 : 16|8@1+ (1,0) [0|255] ""  PC,MBMU
 SG_ S2A_SUMDATA4_CUS_Reserve4_27 : 24|8@1+ (1,0) [0|255] ""  PC,MBMU
 SG_ S2A_SUMDATA4_CUS_Reserve5_27 : 32|8@1+ (1,0) [0|255] ""  PC,MBMU
 SG_ S2A_SUMDATA4_CUS_Reserve6_27 : 40|8@1+ (1,0) [0|255] ""  PC,MBMU
 SG_ S2A_SUMDATA4_CUS_Reserve7_27 : 48|8@1+ (1,0) [0|255] ""  PC,MBMU
 SG_ S2A_SUMDATA4_CUS_Reserve8_27 : 56|8@1+ (1,0) [0|255] ""  PC,MBMU

BO_ 2339700572 S2A_SUMDATA4_CUS__28: 8 SBMU
 SG_ S2A_SUMDATA4_CUS_Reserve1_28 : 0|8@1+ (1,0) [0|255] ""  PC,MBMU
 SG_ S2A_SUMDATA4_CUS_Reserve2_28 : 8|8@1+ (1,0) [0|255] ""  PC,MBMU
 SG_ S2A_SUMDATA4_CUS_Reserve3_28 : 16|8@1+ (1,0) [0|255] ""  PC,MBMU
 SG_ S2A_SUMDATA4_CUS_Reserve4_28 : 24|8@1+ (1,0) [0|255] ""  PC,MBMU
 SG_ S2A_SUMDATA4_CUS_Reserve5_28 : 32|8@1+ (1,0) [0|255] ""  PC,MBMU
 SG_ S2A_SUMDATA4_CUS_Reserve6_28 : 40|8@1+ (1,0) [0|255] ""  PC,MBMU
 SG_ S2A_SUMDATA4_CUS_Reserve7_28 : 48|8@1+ (1,0) [0|255] ""  PC,MBMU
 SG_ S2A_SUMDATA4_CUS_Reserve8_28 : 56|8@1+ (1,0) [0|255] ""  PC,MBMU

BO_ 2339700573 S2A_SUMDATA4_CUS__29: 8 SBMU
 SG_ S2A_SUMDATA4_CUS_Reserve1_29 : 0|8@1+ (1,0) [0|255] ""  PC,MBMU
 SG_ S2A_SUMDATA4_CUS_Reserve2_29 : 8|8@1+ (1,0) [0|255] ""  PC,MBMU
 SG_ S2A_SUMDATA4_CUS_Reserve3_29 : 16|8@1+ (1,0) [0|255] ""  PC,MBMU
 SG_ S2A_SUMDATA4_CUS_Reserve4_29 : 24|8@1+ (1,0) [0|255] ""  PC,MBMU
 SG_ S2A_SUMDATA4_CUS_Reserve5_29 : 32|8@1+ (1,0) [0|255] ""  PC,MBMU
 SG_ S2A_SUMDATA4_CUS_Reserve6_29 : 40|8@1+ (1,0) [0|255] ""  PC,MBMU
 SG_ S2A_SUMDATA4_CUS_Reserve7_29 : 48|8@1+ (1,0) [0|255] ""  PC,MBMU
 SG_ S2A_SUMDATA4_CUS_Reserve8_29 : 56|8@1+ (1,0) [0|255] ""  PC,MBMU

BO_ 2339700574 S2A_SUMDATA4_CUS__30: 8 SBMU
 SG_ S2A_SUMDATA4_CUS_Reserve1_30 : 0|8@1+ (1,0) [0|255] ""  PC,MBMU
 SG_ S2A_SUMDATA4_CUS_Reserve2_30 : 8|8@1+ (1,0) [0|255] ""  PC,MBMU
 SG_ S2A_SUMDATA4_CUS_Reserve3_30 : 16|8@1+ (1,0) [0|255] ""  PC,MBMU
 SG_ S2A_SUMDATA4_CUS_Reserve4_30 : 24|8@1+ (1,0) [0|255] ""  PC,MBMU
 SG_ S2A_SUMDATA4_CUS_Reserve5_30 : 32|8@1+ (1,0) [0|255] ""  PC,MBMU
 SG_ S2A_SUMDATA4_CUS_Reserve6_30 : 40|8@1+ (1,0) [0|255] ""  PC,MBMU
 SG_ S2A_SUMDATA4_CUS_Reserve7_30 : 48|8@1+ (1,0) [0|255] ""  PC,MBMU
 SG_ S2A_SUMDATA4_CUS_Reserve8_30 : 56|8@1+ (1,0) [0|255] ""  PC,MBMU

BO_ 2339700575 S2A_SUMDATA4_CUS__31: 8 SBMU
 SG_ S2A_SUMDATA4_CUS_Reserve1_31 : 0|8@1+ (1,0) [0|255] ""  PC,MBMU
 SG_ S2A_SUMDATA4_CUS_Reserve2_31 : 8|8@1+ (1,0) [0|255] ""  PC,MBMU
 SG_ S2A_SUMDATA4_CUS_Reserve3_31 : 16|8@1+ (1,0) [0|255] ""  PC,MBMU
 SG_ S2A_SUMDATA4_CUS_Reserve4_31 : 24|8@1+ (1,0) [0|255] ""  PC,MBMU
 SG_ S2A_SUMDATA4_CUS_Reserve5_31 : 32|8@1+ (1,0) [0|255] ""  PC,MBMU
 SG_ S2A_SUMDATA4_CUS_Reserve6_31 : 40|8@1+ (1,0) [0|255] ""  PC,MBMU
 SG_ S2A_SUMDATA4_CUS_Reserve7_31 : 48|8@1+ (1,0) [0|255] ""  PC,MBMU
 SG_ S2A_SUMDATA4_CUS_Reserve8_31 : 56|8@1+ (1,0) [0|255] ""  PC,MBMU

BO_ 2339700576 S2A_SUMDATA4_CUS__32: 8 SBMU
 SG_ S2A_SUMDATA4_CUS_Reserve1_32 : 0|8@1+ (1,0) [0|255] ""  PC,MBMU
 SG_ S2A_SUMDATA4_CUS_Reserve2_32 : 8|8@1+ (1,0) [0|255] ""  PC,MBMU
 SG_ S2A_SUMDATA4_CUS_Reserve3_32 : 16|8@1+ (1,0) [0|255] ""  PC,MBMU
 SG_ S2A_SUMDATA4_CUS_Reserve4_32 : 24|8@1+ (1,0) [0|255] ""  PC,MBMU
 SG_ S2A_SUMDATA4_CUS_Reserve5_32 : 32|8@1+ (1,0) [0|255] ""  PC,MBMU
 SG_ S2A_SUMDATA4_CUS_Reserve6_32 : 40|8@1+ (1,0) [0|255] ""  PC,MBMU
 SG_ S2A_SUMDATA4_CUS_Reserve7_32 : 48|8@1+ (1,0) [0|255] ""  PC,MBMU
 SG_ S2A_SUMDATA4_CUS_Reserve8_32 : 56|8@1+ (1,0) [0|255] ""  PC,MBMU

BO_ 2339700577 S2A_SUMDATA4_CUS__33: 8 SBMU
 SG_ S2A_SUMDATA4_CUS_Reserve1_33 : 0|8@1+ (1,0) [0|255] ""  PC,MBMU
 SG_ S2A_SUMDATA4_CUS_Reserve2_33 : 8|8@1+ (1,0) [0|255] ""  PC,MBMU
 SG_ S2A_SUMDATA4_CUS_Reserve3_33 : 16|8@1+ (1,0) [0|255] ""  PC,MBMU
 SG_ S2A_SUMDATA4_CUS_Reserve4_33 : 24|8@1+ (1,0) [0|255] ""  PC,MBMU
 SG_ S2A_SUMDATA4_CUS_Reserve5_33 : 32|8@1+ (1,0) [0|255] ""  PC,MBMU
 SG_ S2A_SUMDATA4_CUS_Reserve6_33 : 40|8@1+ (1,0) [0|255] ""  PC,MBMU
 SG_ S2A_SUMDATA4_CUS_Reserve7_33 : 48|8@1+ (1,0) [0|255] ""  PC,MBMU
 SG_ S2A_SUMDATA4_CUS_Reserve8_33 : 56|8@1+ (1,0) [0|255] ""  PC,MBMU

BO_ 2339700578 S2A_SUMDATA4_CUS__34: 8 SBMU
 SG_ S2A_SUMDATA4_CUS_Reserve1_34 : 0|8@1+ (1,0) [0|255] ""  PC,MBMU
 SG_ S2A_SUMDATA4_CUS_Reserve2_34 : 8|8@1+ (1,0) [0|255] ""  PC,MBMU
 SG_ S2A_SUMDATA4_CUS_Reserve3_34 : 16|8@1+ (1,0) [0|255] ""  PC,MBMU
 SG_ S2A_SUMDATA4_CUS_Reserve4_34 : 24|8@1+ (1,0) [0|255] ""  PC,MBMU
 SG_ S2A_SUMDATA4_CUS_Reserve5_34 : 32|8@1+ (1,0) [0|255] ""  PC,MBMU
 SG_ S2A_SUMDATA4_CUS_Reserve6_34 : 40|8@1+ (1,0) [0|255] ""  PC,MBMU
 SG_ S2A_SUMDATA4_CUS_Reserve7_34 : 48|8@1+ (1,0) [0|255] ""  PC,MBMU
 SG_ S2A_SUMDATA4_CUS_Reserve8_34 : 56|8@1+ (1,0) [0|255] ""  PC,MBMU

BO_ 2339700579 S2A_SUMDATA4_CUS__35: 8 SBMU
 SG_ S2A_SUMDATA4_CUS_Reserve1_35 : 0|8@1+ (1,0) [0|255] ""  PC,MBMU
 SG_ S2A_SUMDATA4_CUS_Reserve2_35 : 8|8@1+ (1,0) [0|255] ""  PC,MBMU
 SG_ S2A_SUMDATA4_CUS_Reserve3_35 : 16|8@1+ (1,0) [0|255] ""  PC,MBMU
 SG_ S2A_SUMDATA4_CUS_Reserve4_35 : 24|8@1+ (1,0) [0|255] ""  PC,MBMU
 SG_ S2A_SUMDATA4_CUS_Reserve5_35 : 32|8@1+ (1,0) [0|255] ""  PC,MBMU
 SG_ S2A_SUMDATA4_CUS_Reserve6_35 : 40|8@1+ (1,0) [0|255] ""  PC,MBMU
 SG_ S2A_SUMDATA4_CUS_Reserve7_35 : 48|8@1+ (1,0) [0|255] ""  PC,MBMU
 SG_ S2A_SUMDATA4_CUS_Reserve8_35 : 56|8@1+ (1,0) [0|255] ""  PC,MBMU

BO_ 2339700580 S2A_SUMDATA4_CUS__36: 8 SBMU
 SG_ S2A_SUMDATA4_CUS_Reserve1_36 : 0|8@1+ (1,0) [0|255] ""  PC,MBMU
 SG_ S2A_SUMDATA4_CUS_Reserve2_36 : 8|8@1+ (1,0) [0|255] ""  PC,MBMU
 SG_ S2A_SUMDATA4_CUS_Reserve3_36 : 16|8@1+ (1,0) [0|255] ""  PC,MBMU
 SG_ S2A_SUMDATA4_CUS_Reserve4_36 : 24|8@1+ (1,0) [0|255] ""  PC,MBMU
 SG_ S2A_SUMDATA4_CUS_Reserve5_36 : 32|8@1+ (1,0) [0|255] ""  PC,MBMU
 SG_ S2A_SUMDATA4_CUS_Reserve6_36 : 40|8@1+ (1,0) [0|255] ""  PC,MBMU
 SG_ S2A_SUMDATA4_CUS_Reserve7_36 : 48|8@1+ (1,0) [0|255] ""  PC,MBMU
 SG_ S2A_SUMDATA4_CUS_Reserve8_36 : 56|8@1+ (1,0) [0|255] ""  PC,MBMU

BO_ 2339700581 S2A_SUMDATA4_CUS__37: 8 SBMU
 SG_ S2A_SUMDATA4_CUS_Reserve1_37 : 0|8@1+ (1,0) [0|255] ""  PC,MBMU
 SG_ S2A_SUMDATA4_CUS_Reserve2_37 : 8|8@1+ (1,0) [0|255] ""  PC,MBMU
 SG_ S2A_SUMDATA4_CUS_Reserve3_37 : 16|8@1+ (1,0) [0|255] ""  PC,MBMU
 SG_ S2A_SUMDATA4_CUS_Reserve4_37 : 24|8@1+ (1,0) [0|255] ""  PC,MBMU
 SG_ S2A_SUMDATA4_CUS_Reserve5_37 : 32|8@1+ (1,0) [0|255] ""  PC,MBMU
 SG_ S2A_SUMDATA4_CUS_Reserve6_37 : 40|8@1+ (1,0) [0|255] ""  PC,MBMU
 SG_ S2A_SUMDATA4_CUS_Reserve7_37 : 48|8@1+ (1,0) [0|255] ""  PC,MBMU
 SG_ S2A_SUMDATA4_CUS_Reserve8_37 : 56|8@1+ (1,0) [0|255] ""  PC,MBMU

BO_ 2339700582 S2A_SUMDATA4_CUS__38: 8 SBMU
 SG_ S2A_SUMDATA4_CUS_Reserve1_38 : 0|8@1+ (1,0) [0|255] ""  PC,MBMU
 SG_ S2A_SUMDATA4_CUS_Reserve2_38 : 8|8@1+ (1,0) [0|255] ""  PC,MBMU
 SG_ S2A_SUMDATA4_CUS_Reserve3_38 : 16|8@1+ (1,0) [0|255] ""  PC,MBMU
 SG_ S2A_SUMDATA4_CUS_Reserve4_38 : 24|8@1+ (1,0) [0|255] ""  PC,MBMU
 SG_ S2A_SUMDATA4_CUS_Reserve5_38 : 32|8@1+ (1,0) [0|255] ""  PC,MBMU
 SG_ S2A_SUMDATA4_CUS_Reserve6_38 : 40|8@1+ (1,0) [0|255] ""  PC,MBMU
 SG_ S2A_SUMDATA4_CUS_Reserve7_38 : 48|8@1+ (1,0) [0|255] ""  PC,MBMU
 SG_ S2A_SUMDATA4_CUS_Reserve8_38 : 56|8@1+ (1,0) [0|255] ""  PC,MBMU

BO_ 2339700583 S2A_SUMDATA4_CUS__39: 8 SBMU
 SG_ S2A_SUMDATA4_CUS_Reserve1_39 : 0|8@1+ (1,0) [0|255] ""  PC,MBMU
 SG_ S2A_SUMDATA4_CUS_Reserve2_39 : 8|8@1+ (1,0) [0|255] ""  PC,MBMU
 SG_ S2A_SUMDATA4_CUS_Reserve3_39 : 16|8@1+ (1,0) [0|255] ""  PC,MBMU
 SG_ S2A_SUMDATA4_CUS_Reserve4_39 : 24|8@1+ (1,0) [0|255] ""  PC,MBMU
 SG_ S2A_SUMDATA4_CUS_Reserve5_39 : 32|8@1+ (1,0) [0|255] ""  PC,MBMU
 SG_ S2A_SUMDATA4_CUS_Reserve6_39 : 40|8@1+ (1,0) [0|255] ""  PC,MBMU
 SG_ S2A_SUMDATA4_CUS_Reserve7_39 : 48|8@1+ (1,0) [0|255] ""  PC,MBMU
 SG_ S2A_SUMDATA4_CUS_Reserve8_39 : 56|8@1+ (1,0) [0|255] ""  PC,MBMU

BO_ 2339700584 S2A_SUMDATA4_CUS__40: 8 SBMU
 SG_ S2A_SUMDATA4_CUS_Reserve1_40 : 0|8@1+ (1,0) [0|255] ""  PC,MBMU
 SG_ S2A_SUMDATA4_CUS_Reserve2_40 : 8|8@1+ (1,0) [0|255] ""  PC,MBMU
 SG_ S2A_SUMDATA4_CUS_Reserve3_40 : 16|8@1+ (1,0) [0|255] ""  PC,MBMU
 SG_ S2A_SUMDATA4_CUS_Reserve4_40 : 24|8@1+ (1,0) [0|255] ""  PC,MBMU
 SG_ S2A_SUMDATA4_CUS_Reserve5_40 : 32|8@1+ (1,0) [0|255] ""  PC,MBMU
 SG_ S2A_SUMDATA4_CUS_Reserve6_40 : 40|8@1+ (1,0) [0|255] ""  PC,MBMU
 SG_ S2A_SUMDATA4_CUS_Reserve7_40 : 48|8@1+ (1,0) [0|255] ""  PC,MBMU
 SG_ S2A_SUMDATA4_CUS_Reserve8_40 : 56|8@1+ (1,0) [0|255] ""  PC,MBMU

BO_ 2339700585 S2A_SUMDATA4_CUS__41: 8 SBMU
 SG_ S2A_SUMDATA4_CUS_Reserve1_41 : 0|8@1+ (1,0) [0|255] ""  PC,MBMU
 SG_ S2A_SUMDATA4_CUS_Reserve2_41 : 8|8@1+ (1,0) [0|255] ""  PC,MBMU
 SG_ S2A_SUMDATA4_CUS_Reserve3_41 : 16|8@1+ (1,0) [0|255] ""  PC,MBMU
 SG_ S2A_SUMDATA4_CUS_Reserve4_41 : 24|8@1+ (1,0) [0|255] ""  PC,MBMU
 SG_ S2A_SUMDATA4_CUS_Reserve5_41 : 32|8@1+ (1,0) [0|255] ""  PC,MBMU
 SG_ S2A_SUMDATA4_CUS_Reserve6_41 : 40|8@1+ (1,0) [0|255] ""  PC,MBMU
 SG_ S2A_SUMDATA4_CUS_Reserve7_41 : 48|8@1+ (1,0) [0|255] ""  PC,MBMU
 SG_ S2A_SUMDATA4_CUS_Reserve8_41 : 56|8@1+ (1,0) [0|255] ""  PC,MBMU

BO_ 2339700586 S2A_SUMDATA4_CUS__42: 8 SBMU
 SG_ S2A_SUMDATA4_CUS_Reserve1_42 : 0|8@1+ (1,0) [0|255] ""  PC,MBMU
 SG_ S2A_SUMDATA4_CUS_Reserve2_42 : 8|8@1+ (1,0) [0|255] ""  PC,MBMU
 SG_ S2A_SUMDATA4_CUS_Reserve3_42 : 16|8@1+ (1,0) [0|255] ""  PC,MBMU
 SG_ S2A_SUMDATA4_CUS_Reserve4_42 : 24|8@1+ (1,0) [0|255] ""  PC,MBMU
 SG_ S2A_SUMDATA4_CUS_Reserve5_42 : 32|8@1+ (1,0) [0|255] ""  PC,MBMU
 SG_ S2A_SUMDATA4_CUS_Reserve6_42 : 40|8@1+ (1,0) [0|255] ""  PC,MBMU
 SG_ S2A_SUMDATA4_CUS_Reserve7_42 : 48|8@1+ (1,0) [0|255] ""  PC,MBMU
 SG_ S2A_SUMDATA4_CUS_Reserve8_42 : 56|8@1+ (1,0) [0|255] ""  PC,MBMU

BO_ 2339700587 S2A_SUMDATA4_CUS__43: 8 SBMU
 SG_ S2A_SUMDATA4_CUS_Reserve1_43 : 0|8@1+ (1,0) [0|255] ""  PC,MBMU
 SG_ S2A_SUMDATA4_CUS_Reserve2_43 : 8|8@1+ (1,0) [0|255] ""  PC,MBMU
 SG_ S2A_SUMDATA4_CUS_Reserve3_43 : 16|8@1+ (1,0) [0|255] ""  PC,MBMU
 SG_ S2A_SUMDATA4_CUS_Reserve4_43 : 24|8@1+ (1,0) [0|255] ""  PC,MBMU
 SG_ S2A_SUMDATA4_CUS_Reserve5_43 : 32|8@1+ (1,0) [0|255] ""  PC,MBMU
 SG_ S2A_SUMDATA4_CUS_Reserve6_43 : 40|8@1+ (1,0) [0|255] ""  PC,MBMU
 SG_ S2A_SUMDATA4_CUS_Reserve7_43 : 48|8@1+ (1,0) [0|255] ""  PC,MBMU
 SG_ S2A_SUMDATA4_CUS_Reserve8_43 : 56|8@1+ (1,0) [0|255] ""  PC,MBMU

BO_ 2339700588 S2A_SUMDATA4_CUS__44: 8 SBMU
 SG_ S2A_SUMDATA4_CUS_Reserve1_44 : 0|8@1+ (1,0) [0|255] ""  PC,MBMU
 SG_ S2A_SUMDATA4_CUS_Reserve2_44 : 8|8@1+ (1,0) [0|255] ""  PC,MBMU
 SG_ S2A_SUMDATA4_CUS_Reserve3_44 : 16|8@1+ (1,0) [0|255] ""  PC,MBMU
 SG_ S2A_SUMDATA4_CUS_Reserve4_44 : 24|8@1+ (1,0) [0|255] ""  PC,MBMU
 SG_ S2A_SUMDATA4_CUS_Reserve5_44 : 32|8@1+ (1,0) [0|255] ""  PC,MBMU
 SG_ S2A_SUMDATA4_CUS_Reserve6_44 : 40|8@1+ (1,0) [0|255] ""  PC,MBMU
 SG_ S2A_SUMDATA4_CUS_Reserve7_44 : 48|8@1+ (1,0) [0|255] ""  PC,MBMU
 SG_ S2A_SUMDATA4_CUS_Reserve8_44 : 56|8@1+ (1,0) [0|255] ""  PC,MBMU

BO_ 2339700589 S2A_SUMDATA4_CUS__45: 8 SBMU
 SG_ S2A_SUMDATA4_CUS_Reserve1_45 : 0|8@1+ (1,0) [0|255] ""  PC,MBMU
 SG_ S2A_SUMDATA4_CUS_Reserve2_45 : 8|8@1+ (1,0) [0|255] ""  PC,MBMU
 SG_ S2A_SUMDATA4_CUS_Reserve3_45 : 16|8@1+ (1,0) [0|255] ""  PC,MBMU
 SG_ S2A_SUMDATA4_CUS_Reserve4_45 : 24|8@1+ (1,0) [0|255] ""  PC,MBMU
 SG_ S2A_SUMDATA4_CUS_Reserve5_45 : 32|8@1+ (1,0) [0|255] ""  PC,MBMU
 SG_ S2A_SUMDATA4_CUS_Reserve6_45 : 40|8@1+ (1,0) [0|255] ""  PC,MBMU
 SG_ S2A_SUMDATA4_CUS_Reserve7_45 : 48|8@1+ (1,0) [0|255] ""  PC,MBMU
 SG_ S2A_SUMDATA4_CUS_Reserve8_45 : 56|8@1+ (1,0) [0|255] ""  PC,MBMU

BO_ 2339700590 S2A_SUMDATA4_CUS__46: 8 SBMU
 SG_ S2A_SUMDATA4_CUS_Reserve1_46 : 0|8@1+ (1,0) [0|255] ""  PC,MBMU
 SG_ S2A_SUMDATA4_CUS_Reserve2_46 : 8|8@1+ (1,0) [0|255] ""  PC,MBMU
 SG_ S2A_SUMDATA4_CUS_Reserve3_46 : 16|8@1+ (1,0) [0|255] ""  PC,MBMU
 SG_ S2A_SUMDATA4_CUS_Reserve4_46 : 24|8@1+ (1,0) [0|255] ""  PC,MBMU
 SG_ S2A_SUMDATA4_CUS_Reserve5_46 : 32|8@1+ (1,0) [0|255] ""  PC,MBMU
 SG_ S2A_SUMDATA4_CUS_Reserve6_46 : 40|8@1+ (1,0) [0|255] ""  PC,MBMU
 SG_ S2A_SUMDATA4_CUS_Reserve7_46 : 48|8@1+ (1,0) [0|255] ""  PC,MBMU
 SG_ S2A_SUMDATA4_CUS_Reserve8_46 : 56|8@1+ (1,0) [0|255] ""  PC,MBMU

BO_ 2339700591 S2A_SUMDATA4_CUS__47: 8 SBMU
 SG_ S2A_SUMDATA4_CUS_Reserve1_47 : 0|8@1+ (1,0) [0|255] ""  PC,MBMU
 SG_ S2A_SUMDATA4_CUS_Reserve2_47 : 8|8@1+ (1,0) [0|255] ""  PC,MBMU
 SG_ S2A_SUMDATA4_CUS_Reserve3_47 : 16|8@1+ (1,0) [0|255] ""  PC,MBMU
 SG_ S2A_SUMDATA4_CUS_Reserve4_47 : 24|8@1+ (1,0) [0|255] ""  PC,MBMU
 SG_ S2A_SUMDATA4_CUS_Reserve5_47 : 32|8@1+ (1,0) [0|255] ""  PC,MBMU
 SG_ S2A_SUMDATA4_CUS_Reserve6_47 : 40|8@1+ (1,0) [0|255] ""  PC,MBMU
 SG_ S2A_SUMDATA4_CUS_Reserve7_47 : 48|8@1+ (1,0) [0|255] ""  PC,MBMU
 SG_ S2A_SUMDATA4_CUS_Reserve8_47 : 56|8@1+ (1,0) [0|255] ""  PC,MBMU

BO_ 2339700592 S2A_SUMDATA4_CUS__48: 8 SBMU
 SG_ S2A_SUMDATA4_CUS_Reserve1_48 : 0|8@1+ (1,0) [0|255] ""  PC,MBMU
 SG_ S2A_SUMDATA4_CUS_Reserve2_48 : 8|8@1+ (1,0) [0|255] ""  PC,MBMU
 SG_ S2A_SUMDATA4_CUS_Reserve3_48 : 16|8@1+ (1,0) [0|255] ""  PC,MBMU
 SG_ S2A_SUMDATA4_CUS_Reserve4_48 : 24|8@1+ (1,0) [0|255] ""  PC,MBMU
 SG_ S2A_SUMDATA4_CUS_Reserve5_48 : 32|8@1+ (1,0) [0|255] ""  PC,MBMU
 SG_ S2A_SUMDATA4_CUS_Reserve6_48 : 40|8@1+ (1,0) [0|255] ""  PC,MBMU
 SG_ S2A_SUMDATA4_CUS_Reserve7_48 : 48|8@1+ (1,0) [0|255] ""  PC,MBMU
 SG_ S2A_SUMDATA4_CUS_Reserve8_48 : 56|8@1+ (1,0) [0|255] ""  PC,MBMU

BO_ 2339700593 S2A_SUMDATA4_CUS__49: 8 SBMU
 SG_ S2A_SUMDATA4_CUS_Reserve1_49 : 0|8@1+ (1,0) [0|255] ""  PC,MBMU
 SG_ S2A_SUMDATA4_CUS_Reserve2_49 : 8|8@1+ (1,0) [0|255] ""  PC,MBMU
 SG_ S2A_SUMDATA4_CUS_Reserve3_49 : 16|8@1+ (1,0) [0|255] ""  PC,MBMU
 SG_ S2A_SUMDATA4_CUS_Reserve4_49 : 24|8@1+ (1,0) [0|255] ""  PC,MBMU
 SG_ S2A_SUMDATA4_CUS_Reserve5_49 : 32|8@1+ (1,0) [0|255] ""  PC,MBMU
 SG_ S2A_SUMDATA4_CUS_Reserve6_49 : 40|8@1+ (1,0) [0|255] ""  PC,MBMU
 SG_ S2A_SUMDATA4_CUS_Reserve7_49 : 48|8@1+ (1,0) [0|255] ""  PC,MBMU
 SG_ S2A_SUMDATA4_CUS_Reserve8_49 : 56|8@1+ (1,0) [0|255] ""  PC,MBMU

BO_ 2339700594 S2A_SUMDATA4_CUS__50: 8 SBMU
 SG_ S2A_SUMDATA4_CUS_Reserve1_50 : 0|8@1+ (1,0) [0|255] ""  PC,MBMU
 SG_ S2A_SUMDATA4_CUS_Reserve2_50 : 8|8@1+ (1,0) [0|255] ""  PC,MBMU
 SG_ S2A_SUMDATA4_CUS_Reserve3_50 : 16|8@1+ (1,0) [0|255] ""  PC,MBMU
 SG_ S2A_SUMDATA4_CUS_Reserve4_50 : 24|8@1+ (1,0) [0|255] ""  PC,MBMU
 SG_ S2A_SUMDATA4_CUS_Reserve5_50 : 32|8@1+ (1,0) [0|255] ""  PC,MBMU
 SG_ S2A_SUMDATA4_CUS_Reserve6_50 : 40|8@1+ (1,0) [0|255] ""  PC,MBMU
 SG_ S2A_SUMDATA4_CUS_Reserve7_50 : 48|8@1+ (1,0) [0|255] ""  PC,MBMU
 SG_ S2A_SUMDATA4_CUS_Reserve8_50 : 56|8@1+ (1,0) [0|255] ""  PC,MBMU

BO_ 2339700595 S2A_SUMDATA4_CUS__51: 8 SBMU
 SG_ S2A_SUMDATA4_CUS_Reserve1_51 : 0|8@1+ (1,0) [0|255] ""  PC,MBMU
 SG_ S2A_SUMDATA4_CUS_Reserve2_51 : 8|8@1+ (1,0) [0|255] ""  PC,MBMU
 SG_ S2A_SUMDATA4_CUS_Reserve3_51 : 16|8@1+ (1,0) [0|255] ""  PC,MBMU
 SG_ S2A_SUMDATA4_CUS_Reserve4_51 : 24|8@1+ (1,0) [0|255] ""  PC,MBMU
 SG_ S2A_SUMDATA4_CUS_Reserve5_51 : 32|8@1+ (1,0) [0|255] ""  PC,MBMU
 SG_ S2A_SUMDATA4_CUS_Reserve6_51 : 40|8@1+ (1,0) [0|255] ""  PC,MBMU
 SG_ S2A_SUMDATA4_CUS_Reserve7_51 : 48|8@1+ (1,0) [0|255] ""  PC,MBMU
 SG_ S2A_SUMDATA4_CUS_Reserve8_51 : 56|8@1+ (1,0) [0|255] ""  PC,MBMU

BO_ 2339700596 S2A_SUMDATA4_CUS__52: 8 SBMU
 SG_ S2A_SUMDATA4_CUS_Reserve1_52 : 0|8@1+ (1,0) [0|255] ""  PC,MBMU
 SG_ S2A_SUMDATA4_CUS_Reserve2_52 : 8|8@1+ (1,0) [0|255] ""  PC,MBMU
 SG_ S2A_SUMDATA4_CUS_Reserve3_52 : 16|8@1+ (1,0) [0|255] ""  PC,MBMU
 SG_ S2A_SUMDATA4_CUS_Reserve4_52 : 24|8@1+ (1,0) [0|255] ""  PC,MBMU
 SG_ S2A_SUMDATA4_CUS_Reserve5_52 : 32|8@1+ (1,0) [0|255] ""  PC,MBMU
 SG_ S2A_SUMDATA4_CUS_Reserve6_52 : 40|8@1+ (1,0) [0|255] ""  PC,MBMU
 SG_ S2A_SUMDATA4_CUS_Reserve7_52 : 48|8@1+ (1,0) [0|255] ""  PC,MBMU
 SG_ S2A_SUMDATA4_CUS_Reserve8_52 : 56|8@1+ (1,0) [0|255] ""  PC,MBMU

BO_ 2339700597 S2A_SUMDATA4_CUS__53: 8 SBMU
 SG_ S2A_SUMDATA4_CUS_Reserve1_53 : 0|8@1+ (1,0) [0|255] ""  PC,MBMU
 SG_ S2A_SUMDATA4_CUS_Reserve2_53 : 8|8@1+ (1,0) [0|255] ""  PC,MBMU
 SG_ S2A_SUMDATA4_CUS_Reserve3_53 : 16|8@1+ (1,0) [0|255] ""  PC,MBMU
 SG_ S2A_SUMDATA4_CUS_Reserve4_53 : 24|8@1+ (1,0) [0|255] ""  PC,MBMU
 SG_ S2A_SUMDATA4_CUS_Reserve5_53 : 32|8@1+ (1,0) [0|255] ""  PC,MBMU
 SG_ S2A_SUMDATA4_CUS_Reserve6_53 : 40|8@1+ (1,0) [0|255] ""  PC,MBMU
 SG_ S2A_SUMDATA4_CUS_Reserve7_53 : 48|8@1+ (1,0) [0|255] ""  PC,MBMU
 SG_ S2A_SUMDATA4_CUS_Reserve8_53 : 56|8@1+ (1,0) [0|255] ""  PC,MBMU

BO_ 2339700598 S2A_SUMDATA4_CUS__54: 8 SBMU
 SG_ S2A_SUMDATA4_CUS_Reserve1_54 : 0|8@1+ (1,0) [0|255] ""  PC,MBMU
 SG_ S2A_SUMDATA4_CUS_Reserve2_54 : 8|8@1+ (1,0) [0|255] ""  PC,MBMU
 SG_ S2A_SUMDATA4_CUS_Reserve3_54 : 16|8@1+ (1,0) [0|255] ""  PC,MBMU
 SG_ S2A_SUMDATA4_CUS_Reserve4_54 : 24|8@1+ (1,0) [0|255] ""  PC,MBMU
 SG_ S2A_SUMDATA4_CUS_Reserve5_54 : 32|8@1+ (1,0) [0|255] ""  PC,MBMU
 SG_ S2A_SUMDATA4_CUS_Reserve6_54 : 40|8@1+ (1,0) [0|255] ""  PC,MBMU
 SG_ S2A_SUMDATA4_CUS_Reserve7_54 : 48|8@1+ (1,0) [0|255] ""  PC,MBMU
 SG_ S2A_SUMDATA4_CUS_Reserve8_54 : 56|8@1+ (1,0) [0|255] ""  PC,MBMU

BO_ 2339700599 S2A_SUMDATA4_CUS__55: 8 SBMU
 SG_ S2A_SUMDATA4_CUS_Reserve1_55 : 0|8@1+ (1,0) [0|255] ""  PC,MBMU
 SG_ S2A_SUMDATA4_CUS_Reserve2_55 : 8|8@1+ (1,0) [0|255] ""  PC,MBMU
 SG_ S2A_SUMDATA4_CUS_Reserve3_55 : 16|8@1+ (1,0) [0|255] ""  PC,MBMU
 SG_ S2A_SUMDATA4_CUS_Reserve4_55 : 24|8@1+ (1,0) [0|255] ""  PC,MBMU
 SG_ S2A_SUMDATA4_CUS_Reserve5_55 : 32|8@1+ (1,0) [0|255] ""  PC,MBMU
 SG_ S2A_SUMDATA4_CUS_Reserve6_55 : 40|8@1+ (1,0) [0|255] ""  PC,MBMU
 SG_ S2A_SUMDATA4_CUS_Reserve7_55 : 48|8@1+ (1,0) [0|255] ""  PC,MBMU
 SG_ S2A_SUMDATA4_CUS_Reserve8_55 : 56|8@1+ (1,0) [0|255] ""  PC,MBMU

BO_ 2339700600 S2A_SUMDATA4_CUS__56: 8 SBMU
 SG_ S2A_SUMDATA4_CUS_Reserve1_56 : 0|8@1+ (1,0) [0|255] ""  PC,MBMU
 SG_ S2A_SUMDATA4_CUS_Reserve2_56 : 8|8@1+ (1,0) [0|255] ""  PC,MBMU
 SG_ S2A_SUMDATA4_CUS_Reserve3_56 : 16|8@1+ (1,0) [0|255] ""  PC,MBMU
 SG_ S2A_SUMDATA4_CUS_Reserve4_56 : 24|8@1+ (1,0) [0|255] ""  PC,MBMU
 SG_ S2A_SUMDATA4_CUS_Reserve5_56 : 32|8@1+ (1,0) [0|255] ""  PC,MBMU
 SG_ S2A_SUMDATA4_CUS_Reserve6_56 : 40|8@1+ (1,0) [0|255] ""  PC,MBMU
 SG_ S2A_SUMDATA4_CUS_Reserve7_56 : 48|8@1+ (1,0) [0|255] ""  PC,MBMU
 SG_ S2A_SUMDATA4_CUS_Reserve8_56 : 56|8@1+ (1,0) [0|255] ""  PC,MBMU

BO_ 2339700601 S2A_SUMDATA4_CUS__57: 8 SBMU
 SG_ S2A_SUMDATA4_CUS_Reserve1_57 : 0|8@1+ (1,0) [0|255] ""  PC,MBMU
 SG_ S2A_SUMDATA4_CUS_Reserve2_57 : 8|8@1+ (1,0) [0|255] ""  PC,MBMU
 SG_ S2A_SUMDATA4_CUS_Reserve3_57 : 16|8@1+ (1,0) [0|255] ""  PC,MBMU
 SG_ S2A_SUMDATA4_CUS_Reserve4_57 : 24|8@1+ (1,0) [0|255] ""  PC,MBMU
 SG_ S2A_SUMDATA4_CUS_Reserve5_57 : 32|8@1+ (1,0) [0|255] ""  PC,MBMU
 SG_ S2A_SUMDATA4_CUS_Reserve6_57 : 40|8@1+ (1,0) [0|255] ""  PC,MBMU
 SG_ S2A_SUMDATA4_CUS_Reserve7_57 : 48|8@1+ (1,0) [0|255] ""  PC,MBMU
 SG_ S2A_SUMDATA4_CUS_Reserve8_57 : 56|8@1+ (1,0) [0|255] ""  PC,MBMU

BO_ 2339700602 S2A_SUMDATA4_CUS__58: 8 SBMU
 SG_ S2A_SUMDATA4_CUS_Reserve1_58 : 0|8@1+ (1,0) [0|255] ""  PC,MBMU
 SG_ S2A_SUMDATA4_CUS_Reserve2_58 : 8|8@1+ (1,0) [0|255] ""  PC,MBMU
 SG_ S2A_SUMDATA4_CUS_Reserve3_58 : 16|8@1+ (1,0) [0|255] ""  PC,MBMU
 SG_ S2A_SUMDATA4_CUS_Reserve4_58 : 24|8@1+ (1,0) [0|255] ""  PC,MBMU
 SG_ S2A_SUMDATA4_CUS_Reserve5_58 : 32|8@1+ (1,0) [0|255] ""  PC,MBMU
 SG_ S2A_SUMDATA4_CUS_Reserve6_58 : 40|8@1+ (1,0) [0|255] ""  PC,MBMU
 SG_ S2A_SUMDATA4_CUS_Reserve7_58 : 48|8@1+ (1,0) [0|255] ""  PC,MBMU
 SG_ S2A_SUMDATA4_CUS_Reserve8_58 : 56|8@1+ (1,0) [0|255] ""  PC,MBMU

BO_ 2339700603 S2A_SUMDATA4_CUS__59: 8 SBMU
 SG_ S2A_SUMDATA4_CUS_Reserve1_59 : 0|8@1+ (1,0) [0|255] ""  PC,MBMU
 SG_ S2A_SUMDATA4_CUS_Reserve2_59 : 8|8@1+ (1,0) [0|255] ""  PC,MBMU
 SG_ S2A_SUMDATA4_CUS_Reserve3_59 : 16|8@1+ (1,0) [0|255] ""  PC,MBMU
 SG_ S2A_SUMDATA4_CUS_Reserve4_59 : 24|8@1+ (1,0) [0|255] ""  PC,MBMU
 SG_ S2A_SUMDATA4_CUS_Reserve5_59 : 32|8@1+ (1,0) [0|255] ""  PC,MBMU
 SG_ S2A_SUMDATA4_CUS_Reserve6_59 : 40|8@1+ (1,0) [0|255] ""  PC,MBMU
 SG_ S2A_SUMDATA4_CUS_Reserve7_59 : 48|8@1+ (1,0) [0|255] ""  PC,MBMU
 SG_ S2A_SUMDATA4_CUS_Reserve8_59 : 56|8@1+ (1,0) [0|255] ""  PC,MBMU

BO_ 2339700604 S2A_SUMDATA4_CUS__60: 8 SBMU
 SG_ S2A_SUMDATA4_CUS_Reserve1_60 : 0|8@1+ (1,0) [0|255] ""  PC,MBMU
 SG_ S2A_SUMDATA4_CUS_Reserve2_60 : 8|8@1+ (1,0) [0|255] ""  PC,MBMU
 SG_ S2A_SUMDATA4_CUS_Reserve3_60 : 16|8@1+ (1,0) [0|255] ""  PC,MBMU
 SG_ S2A_SUMDATA4_CUS_Reserve4_60 : 24|8@1+ (1,0) [0|255] ""  PC,MBMU
 SG_ S2A_SUMDATA4_CUS_Reserve5_60 : 32|8@1+ (1,0) [0|255] ""  PC,MBMU
 SG_ S2A_SUMDATA4_CUS_Reserve6_60 : 40|8@1+ (1,0) [0|255] ""  PC,MBMU
 SG_ S2A_SUMDATA4_CUS_Reserve7_60 : 48|8@1+ (1,0) [0|255] ""  PC,MBMU
 SG_ S2A_SUMDATA4_CUS_Reserve8_60 : 56|8@1+ (1,0) [0|255] ""  PC,MBMU

BO_ 2339700605 S2A_SUMDATA4_CUS__61: 8 SBMU
 SG_ S2A_SUMDATA4_CUS_Reserve1_61 : 0|8@1+ (1,0) [0|255] ""  PC,MBMU
 SG_ S2A_SUMDATA4_CUS_Reserve2_61 : 8|8@1+ (1,0) [0|255] ""  PC,MBMU
 SG_ S2A_SUMDATA4_CUS_Reserve3_61 : 16|8@1+ (1,0) [0|255] ""  PC,MBMU
 SG_ S2A_SUMDATA4_CUS_Reserve4_61 : 24|8@1+ (1,0) [0|255] ""  PC,MBMU
 SG_ S2A_SUMDATA4_CUS_Reserve5_61 : 32|8@1+ (1,0) [0|255] ""  PC,MBMU
 SG_ S2A_SUMDATA4_CUS_Reserve6_61 : 40|8@1+ (1,0) [0|255] ""  PC,MBMU
 SG_ S2A_SUMDATA4_CUS_Reserve7_61 : 48|8@1+ (1,0) [0|255] ""  PC,MBMU
 SG_ S2A_SUMDATA4_CUS_Reserve8_61 : 56|8@1+ (1,0) [0|255] ""  PC,MBMU

BO_ 2339700606 S2A_SUMDATA4_CUS__62: 8 SBMU
 SG_ S2A_SUMDATA4_CUS_Reserve1_62 : 0|8@1+ (1,0) [0|255] ""  PC,MBMU
 SG_ S2A_SUMDATA4_CUS_Reserve2_62 : 8|8@1+ (1,0) [0|255] ""  PC,MBMU
 SG_ S2A_SUMDATA4_CUS_Reserve3_62 : 16|8@1+ (1,0) [0|255] ""  PC,MBMU
 SG_ S2A_SUMDATA4_CUS_Reserve4_62 : 24|8@1+ (1,0) [0|255] ""  PC,MBMU
 SG_ S2A_SUMDATA4_CUS_Reserve5_62 : 32|8@1+ (1,0) [0|255] ""  PC,MBMU
 SG_ S2A_SUMDATA4_CUS_Reserve6_62 : 40|8@1+ (1,0) [0|255] ""  PC,MBMU
 SG_ S2A_SUMDATA4_CUS_Reserve7_62 : 48|8@1+ (1,0) [0|255] ""  PC,MBMU
 SG_ S2A_SUMDATA4_CUS_Reserve8_62 : 56|8@1+ (1,0) [0|255] ""  PC,MBMU

BO_ 2339700607 S2A_SUMDATA4_CUS__63: 8 SBMU
 SG_ S2A_SUMDATA4_CUS_Reserve1_63 : 0|8@1+ (1,0) [0|255] ""  PC,MBMU
 SG_ S2A_SUMDATA4_CUS_Reserve2_63 : 8|8@1+ (1,0) [0|255] ""  PC,MBMU
 SG_ S2A_SUMDATA4_CUS_Reserve3_63 : 16|8@1+ (1,0) [0|255] ""  PC,MBMU
 SG_ S2A_SUMDATA4_CUS_Reserve4_63 : 24|8@1+ (1,0) [0|255] ""  PC,MBMU
 SG_ S2A_SUMDATA4_CUS_Reserve5_63 : 32|8@1+ (1,0) [0|255] ""  PC,MBMU
 SG_ S2A_SUMDATA4_CUS_Reserve6_63 : 40|8@1+ (1,0) [0|255] ""  PC,MBMU
 SG_ S2A_SUMDATA4_CUS_Reserve7_63 : 48|8@1+ (1,0) [0|255] ""  PC,MBMU
 SG_ S2A_SUMDATA4_CUS_Reserve8_63 : 56|8@1+ (1,0) [0|255] ""  PC,MBMU

BO_ 2339766081 S2A_SUMDATA5_CUS__01: 8 SBMU
 SG_ S2A_SUMDATA5_CUS_Reserve1_01 : 0|8@1+ (1,0) [0|255] ""  PC,MBMU
 SG_ S2A_SUMDATA5_CUS_Reserve2_01 : 8|8@1+ (1,0) [0|255] ""  PC,MBMU
 SG_ S2A_SUMDATA5_CUS_Reserve3_01 : 16|8@1+ (1,0) [0|255] ""  PC,MBMU
 SG_ S2A_SUMDATA5_CUS_Reserve4_01 : 24|8@1+ (1,0) [0|255] ""  PC,MBMU
 SG_ S2A_SUMDATA5_CUS_Reserve5_01 : 32|8@1+ (1,0) [0|255] ""  PC,MBMU
 SG_ S2A_SUMDATA5_CUS_Reserve6_01 : 40|8@1+ (1,0) [0|255] ""  PC,MBMU
 SG_ S2A_SUMDATA5_CUS_Reserve7_01 : 48|8@1+ (1,0) [0|255] ""  PC,MBMU
 SG_ S2A_SUMDATA5_CUS_Reserve8_01 : 56|8@1+ (1,0) [0|255] ""  PC,MBMU

BO_ 2339766082 S2A_SUMDATA5_CUS__02: 8 SBMU
 SG_ S2A_SUMDATA5_CUS_Reserve1_02 : 0|8@1+ (1,0) [0|255] ""  PC,MBMU
 SG_ S2A_SUMDATA5_CUS_Reserve2_02 : 8|8@1+ (1,0) [0|255] ""  PC,MBMU
 SG_ S2A_SUMDATA5_CUS_Reserve3_02 : 16|8@1+ (1,0) [0|255] ""  PC,MBMU
 SG_ S2A_SUMDATA5_CUS_Reserve4_02 : 24|8@1+ (1,0) [0|255] ""  PC,MBMU
 SG_ S2A_SUMDATA5_CUS_Reserve5_02 : 32|8@1+ (1,0) [0|255] ""  PC,MBMU
 SG_ S2A_SUMDATA5_CUS_Reserve6_02 : 40|8@1+ (1,0) [0|255] ""  PC,MBMU
 SG_ S2A_SUMDATA5_CUS_Reserve7_02 : 48|8@1+ (1,0) [0|255] ""  PC,MBMU
 SG_ S2A_SUMDATA5_CUS_Reserve8_02 : 56|8@1+ (1,0) [0|255] ""  PC,MBMU

BO_ 2339766083 S2A_SUMDATA5_CUS__03: 8 SBMU
 SG_ S2A_SUMDATA5_CUS_Reserve1_03 : 0|8@1+ (1,0) [0|255] ""  PC,MBMU
 SG_ S2A_SUMDATA5_CUS_Reserve2_03 : 8|8@1+ (1,0) [0|255] ""  PC,MBMU
 SG_ S2A_SUMDATA5_CUS_Reserve3_03 : 16|8@1+ (1,0) [0|255] ""  PC,MBMU
 SG_ S2A_SUMDATA5_CUS_Reserve4_03 : 24|8@1+ (1,0) [0|255] ""  PC,MBMU
 SG_ S2A_SUMDATA5_CUS_Reserve5_03 : 32|8@1+ (1,0) [0|255] ""  PC,MBMU
 SG_ S2A_SUMDATA5_CUS_Reserve6_03 : 40|8@1+ (1,0) [0|255] ""  PC,MBMU
 SG_ S2A_SUMDATA5_CUS_Reserve7_03 : 48|8@1+ (1,0) [0|255] ""  PC,MBMU
 SG_ S2A_SUMDATA5_CUS_Reserve8_03 : 56|8@1+ (1,0) [0|255] ""  PC,MBMU

BO_ 2339766084 S2A_SUMDATA5_CUS__04: 8 SBMU
 SG_ S2A_SUMDATA5_CUS_Reserve1_04 : 0|8@1+ (1,0) [0|255] ""  PC,MBMU
 SG_ S2A_SUMDATA5_CUS_Reserve2_04 : 8|8@1+ (1,0) [0|255] ""  PC,MBMU
 SG_ S2A_SUMDATA5_CUS_Reserve3_04 : 16|8@1+ (1,0) [0|255] ""  PC,MBMU
 SG_ S2A_SUMDATA5_CUS_Reserve4_04 : 24|8@1+ (1,0) [0|255] ""  PC,MBMU
 SG_ S2A_SUMDATA5_CUS_Reserve5_04 : 32|8@1+ (1,0) [0|255] ""  PC,MBMU
 SG_ S2A_SUMDATA5_CUS_Reserve6_04 : 40|8@1+ (1,0) [0|255] ""  PC,MBMU
 SG_ S2A_SUMDATA5_CUS_Reserve7_04 : 48|8@1+ (1,0) [0|255] ""  PC,MBMU
 SG_ S2A_SUMDATA5_CUS_Reserve8_04 : 56|8@1+ (1,0) [0|255] ""  PC,MBMU

BO_ 2339766085 S2A_SUMDATA5_CUS__05: 8 SBMU
 SG_ S2A_SUMDATA5_CUS_Reserve1_05 : 0|8@1+ (1,0) [0|255] ""  PC,MBMU
 SG_ S2A_SUMDATA5_CUS_Reserve2_05 : 8|8@1+ (1,0) [0|255] ""  PC,MBMU
 SG_ S2A_SUMDATA5_CUS_Reserve3_05 : 16|8@1+ (1,0) [0|255] ""  PC,MBMU
 SG_ S2A_SUMDATA5_CUS_Reserve4_05 : 24|8@1+ (1,0) [0|255] ""  PC,MBMU
 SG_ S2A_SUMDATA5_CUS_Reserve5_05 : 32|8@1+ (1,0) [0|255] ""  PC,MBMU
 SG_ S2A_SUMDATA5_CUS_Reserve6_05 : 40|8@1+ (1,0) [0|255] ""  PC,MBMU
 SG_ S2A_SUMDATA5_CUS_Reserve7_05 : 48|8@1+ (1,0) [0|255] ""  PC,MBMU
 SG_ S2A_SUMDATA5_CUS_Reserve8_05 : 56|8@1+ (1,0) [0|255] ""  PC,MBMU

BO_ 2339766086 S2A_SUMDATA5_CUS__06: 8 SBMU
 SG_ S2A_SUMDATA5_CUS_Reserve1_06 : 0|8@1+ (1,0) [0|255] ""  PC,MBMU
 SG_ S2A_SUMDATA5_CUS_Reserve2_06 : 8|8@1+ (1,0) [0|255] ""  PC,MBMU
 SG_ S2A_SUMDATA5_CUS_Reserve3_06 : 16|8@1+ (1,0) [0|255] ""  PC,MBMU
 SG_ S2A_SUMDATA5_CUS_Reserve4_06 : 24|8@1+ (1,0) [0|255] ""  PC,MBMU
 SG_ S2A_SUMDATA5_CUS_Reserve5_06 : 32|8@1+ (1,0) [0|255] ""  PC,MBMU
 SG_ S2A_SUMDATA5_CUS_Reserve6_06 : 40|8@1+ (1,0) [0|255] ""  PC,MBMU
 SG_ S2A_SUMDATA5_CUS_Reserve7_06 : 48|8@1+ (1,0) [0|255] ""  PC,MBMU
 SG_ S2A_SUMDATA5_CUS_Reserve8_06 : 56|8@1+ (1,0) [0|255] ""  PC,MBMU

BO_ 2339766087 S2A_SUMDATA5_CUS__07: 8 SBMU
 SG_ S2A_SUMDATA5_CUS_Reserve1_07 : 0|8@1+ (1,0) [0|255] ""  PC,MBMU
 SG_ S2A_SUMDATA5_CUS_Reserve2_07 : 8|8@1+ (1,0) [0|255] ""  PC,MBMU
 SG_ S2A_SUMDATA5_CUS_Reserve3_07 : 16|8@1+ (1,0) [0|255] ""  PC,MBMU
 SG_ S2A_SUMDATA5_CUS_Reserve4_07 : 24|8@1+ (1,0) [0|255] ""  PC,MBMU
 SG_ S2A_SUMDATA5_CUS_Reserve5_07 : 32|8@1+ (1,0) [0|255] ""  PC,MBMU
 SG_ S2A_SUMDATA5_CUS_Reserve6_07 : 40|8@1+ (1,0) [0|255] ""  PC,MBMU
 SG_ S2A_SUMDATA5_CUS_Reserve7_07 : 48|8@1+ (1,0) [0|255] ""  PC,MBMU
 SG_ S2A_SUMDATA5_CUS_Reserve8_07 : 56|8@1+ (1,0) [0|255] ""  PC,MBMU

BO_ 2339766088 S2A_SUMDATA5_CUS__08: 8 SBMU
 SG_ S2A_SUMDATA5_CUS_Reserve1_08 : 0|8@1+ (1,0) [0|255] ""  PC,MBMU
 SG_ S2A_SUMDATA5_CUS_Reserve2_08 : 8|8@1+ (1,0) [0|255] ""  PC,MBMU
 SG_ S2A_SUMDATA5_CUS_Reserve3_08 : 16|8@1+ (1,0) [0|255] ""  PC,MBMU
 SG_ S2A_SUMDATA5_CUS_Reserve4_08 : 24|8@1+ (1,0) [0|255] ""  PC,MBMU
 SG_ S2A_SUMDATA5_CUS_Reserve5_08 : 32|8@1+ (1,0) [0|255] ""  PC,MBMU
 SG_ S2A_SUMDATA5_CUS_Reserve6_08 : 40|8@1+ (1,0) [0|255] ""  PC,MBMU
 SG_ S2A_SUMDATA5_CUS_Reserve7_08 : 48|8@1+ (1,0) [0|255] ""  PC,MBMU
 SG_ S2A_SUMDATA5_CUS_Reserve8_08 : 56|8@1+ (1,0) [0|255] ""  PC,MBMU

BO_ 2339766089 S2A_SUMDATA5_CUS__09: 8 SBMU
 SG_ S2A_SUMDATA5_CUS_Reserve1_09 : 0|8@1+ (1,0) [0|255] ""  PC,MBMU
 SG_ S2A_SUMDATA5_CUS_Reserve2_09 : 8|8@1+ (1,0) [0|255] ""  PC,MBMU
 SG_ S2A_SUMDATA5_CUS_Reserve3_09 : 16|8@1+ (1,0) [0|255] ""  PC,MBMU
 SG_ S2A_SUMDATA5_CUS_Reserve4_09 : 24|8@1+ (1,0) [0|255] ""  PC,MBMU
 SG_ S2A_SUMDATA5_CUS_Reserve5_09 : 32|8@1+ (1,0) [0|255] ""  PC,MBMU
 SG_ S2A_SUMDATA5_CUS_Reserve6_09 : 40|8@1+ (1,0) [0|255] ""  PC,MBMU
 SG_ S2A_SUMDATA5_CUS_Reserve7_09 : 48|8@1+ (1,0) [0|255] ""  PC,MBMU
 SG_ S2A_SUMDATA5_CUS_Reserve8_09 : 56|8@1+ (1,0) [0|255] ""  PC,MBMU

BO_ 2339766090 S2A_SUMDATA5_CUS__10: 8 SBMU
 SG_ S2A_SUMDATA5_CUS_Reserve1_10 : 0|8@1+ (1,0) [0|255] ""  PC,MBMU
 SG_ S2A_SUMDATA5_CUS_Reserve2_10 : 8|8@1+ (1,0) [0|255] ""  PC,MBMU
 SG_ S2A_SUMDATA5_CUS_Reserve3_10 : 16|8@1+ (1,0) [0|255] ""  PC,MBMU
 SG_ S2A_SUMDATA5_CUS_Reserve4_10 : 24|8@1+ (1,0) [0|255] ""  PC,MBMU
 SG_ S2A_SUMDATA5_CUS_Reserve5_10 : 32|8@1+ (1,0) [0|255] ""  PC,MBMU
 SG_ S2A_SUMDATA5_CUS_Reserve6_10 : 40|8@1+ (1,0) [0|255] ""  PC,MBMU
 SG_ S2A_SUMDATA5_CUS_Reserve7_10 : 48|8@1+ (1,0) [0|255] ""  PC,MBMU
 SG_ S2A_SUMDATA5_CUS_Reserve8_10 : 56|8@1+ (1,0) [0|255] ""  PC,MBMU

BO_ 2339766091 S2A_SUMDATA5_CUS__11: 8 SBMU
 SG_ S2A_SUMDATA5_CUS_Reserve1_11 : 0|8@1+ (1,0) [0|255] ""  PC,MBMU
 SG_ S2A_SUMDATA5_CUS_Reserve2_11 : 8|8@1+ (1,0) [0|255] ""  PC,MBMU
 SG_ S2A_SUMDATA5_CUS_Reserve3_11 : 16|8@1+ (1,0) [0|255] ""  PC,MBMU
 SG_ S2A_SUMDATA5_CUS_Reserve4_11 : 24|8@1+ (1,0) [0|255] ""  PC,MBMU
 SG_ S2A_SUMDATA5_CUS_Reserve5_11 : 32|8@1+ (1,0) [0|255] ""  PC,MBMU
 SG_ S2A_SUMDATA5_CUS_Reserve6_11 : 40|8@1+ (1,0) [0|255] ""  PC,MBMU
 SG_ S2A_SUMDATA5_CUS_Reserve7_11 : 48|8@1+ (1,0) [0|255] ""  PC,MBMU
 SG_ S2A_SUMDATA5_CUS_Reserve8_11 : 56|8@1+ (1,0) [0|255] ""  PC,MBMU

BO_ 2339766092 S2A_SUMDATA5_CUS__12: 8 SBMU
 SG_ S2A_SUMDATA5_CUS_Reserve1_12 : 0|8@1+ (1,0) [0|255] ""  PC,MBMU
 SG_ S2A_SUMDATA5_CUS_Reserve2_12 : 8|8@1+ (1,0) [0|255] ""  PC,MBMU
 SG_ S2A_SUMDATA5_CUS_Reserve3_12 : 16|8@1+ (1,0) [0|255] ""  PC,MBMU
 SG_ S2A_SUMDATA5_CUS_Reserve4_12 : 24|8@1+ (1,0) [0|255] ""  PC,MBMU
 SG_ S2A_SUMDATA5_CUS_Reserve5_12 : 32|8@1+ (1,0) [0|255] ""  PC,MBMU
 SG_ S2A_SUMDATA5_CUS_Reserve6_12 : 40|8@1+ (1,0) [0|255] ""  PC,MBMU
 SG_ S2A_SUMDATA5_CUS_Reserve7_12 : 48|8@1+ (1,0) [0|255] ""  PC,MBMU
 SG_ S2A_SUMDATA5_CUS_Reserve8_12 : 56|8@1+ (1,0) [0|255] ""  PC,MBMU

BO_ 2339766093 S2A_SUMDATA5_CUS__13: 8 SBMU
 SG_ S2A_SUMDATA5_CUS_Reserve1_13 : 0|8@1+ (1,0) [0|255] ""  PC,MBMU
 SG_ S2A_SUMDATA5_CUS_Reserve2_13 : 8|8@1+ (1,0) [0|255] ""  PC,MBMU
 SG_ S2A_SUMDATA5_CUS_Reserve3_13 : 16|8@1+ (1,0) [0|255] ""  PC,MBMU
 SG_ S2A_SUMDATA5_CUS_Reserve4_13 : 24|8@1+ (1,0) [0|255] ""  PC,MBMU
 SG_ S2A_SUMDATA5_CUS_Reserve5_13 : 32|8@1+ (1,0) [0|255] ""  PC,MBMU
 SG_ S2A_SUMDATA5_CUS_Reserve6_13 : 40|8@1+ (1,0) [0|255] ""  PC,MBMU
 SG_ S2A_SUMDATA5_CUS_Reserve7_13 : 48|8@1+ (1,0) [0|255] ""  PC,MBMU
 SG_ S2A_SUMDATA5_CUS_Reserve8_13 : 56|8@1+ (1,0) [0|255] ""  PC,MBMU

BO_ 2339766094 S2A_SUMDATA5_CUS__14: 8 SBMU
 SG_ S2A_SUMDATA5_CUS_Reserve1_14 : 0|8@1+ (1,0) [0|255] ""  PC,MBMU
 SG_ S2A_SUMDATA5_CUS_Reserve2_14 : 8|8@1+ (1,0) [0|255] ""  PC,MBMU
 SG_ S2A_SUMDATA5_CUS_Reserve3_14 : 16|8@1+ (1,0) [0|255] ""  PC,MBMU
 SG_ S2A_SUMDATA5_CUS_Reserve4_14 : 24|8@1+ (1,0) [0|255] ""  PC,MBMU
 SG_ S2A_SUMDATA5_CUS_Reserve5_14 : 32|8@1+ (1,0) [0|255] ""  PC,MBMU
 SG_ S2A_SUMDATA5_CUS_Reserve6_14 : 40|8@1+ (1,0) [0|255] ""  PC,MBMU
 SG_ S2A_SUMDATA5_CUS_Reserve7_14 : 48|8@1+ (1,0) [0|255] ""  PC,MBMU
 SG_ S2A_SUMDATA5_CUS_Reserve8_14 : 56|8@1+ (1,0) [0|255] ""  PC,MBMU

BO_ 2339766095 S2A_SUMDATA5_CUS__15: 8 SBMU
 SG_ S2A_SUMDATA5_CUS_Reserve1_15 : 0|8@1+ (1,0) [0|255] ""  PC,MBMU
 SG_ S2A_SUMDATA5_CUS_Reserve2_15 : 8|8@1+ (1,0) [0|255] ""  PC,MBMU
 SG_ S2A_SUMDATA5_CUS_Reserve3_15 : 16|8@1+ (1,0) [0|255] ""  PC,MBMU
 SG_ S2A_SUMDATA5_CUS_Reserve4_15 : 24|8@1+ (1,0) [0|255] ""  PC,MBMU
 SG_ S2A_SUMDATA5_CUS_Reserve5_15 : 32|8@1+ (1,0) [0|255] ""  PC,MBMU
 SG_ S2A_SUMDATA5_CUS_Reserve6_15 : 40|8@1+ (1,0) [0|255] ""  PC,MBMU
 SG_ S2A_SUMDATA5_CUS_Reserve7_15 : 48|8@1+ (1,0) [0|255] ""  PC,MBMU
 SG_ S2A_SUMDATA5_CUS_Reserve8_15 : 56|8@1+ (1,0) [0|255] ""  PC,MBMU

BO_ 2339766096 S2A_SUMDATA5_CUS__16: 8 SBMU
 SG_ S2A_SUMDATA5_CUS_Reserve1_16 : 0|8@1+ (1,0) [0|255] ""  PC,MBMU
 SG_ S2A_SUMDATA5_CUS_Reserve2_16 : 8|8@1+ (1,0) [0|255] ""  PC,MBMU
 SG_ S2A_SUMDATA5_CUS_Reserve3_16 : 16|8@1+ (1,0) [0|255] ""  PC,MBMU
 SG_ S2A_SUMDATA5_CUS_Reserve4_16 : 24|8@1+ (1,0) [0|255] ""  PC,MBMU
 SG_ S2A_SUMDATA5_CUS_Reserve5_16 : 32|8@1+ (1,0) [0|255] ""  PC,MBMU
 SG_ S2A_SUMDATA5_CUS_Reserve6_16 : 40|8@1+ (1,0) [0|255] ""  PC,MBMU
 SG_ S2A_SUMDATA5_CUS_Reserve7_16 : 48|8@1+ (1,0) [0|255] ""  PC,MBMU
 SG_ S2A_SUMDATA5_CUS_Reserve8_16 : 56|8@1+ (1,0) [0|255] ""  PC,MBMU

BO_ 2339766097 S2A_SUMDATA5_CUS__17: 8 SBMU
 SG_ S2A_SUMDATA5_CUS_Reserve1_17 : 0|8@1+ (1,0) [0|255] ""  PC,MBMU
 SG_ S2A_SUMDATA5_CUS_Reserve2_17 : 8|8@1+ (1,0) [0|255] ""  PC,MBMU
 SG_ S2A_SUMDATA5_CUS_Reserve3_17 : 16|8@1+ (1,0) [0|255] ""  PC,MBMU
 SG_ S2A_SUMDATA5_CUS_Reserve4_17 : 24|8@1+ (1,0) [0|255] ""  PC,MBMU
 SG_ S2A_SUMDATA5_CUS_Reserve5_17 : 32|8@1+ (1,0) [0|255] ""  PC,MBMU
 SG_ S2A_SUMDATA5_CUS_Reserve6_17 : 40|8@1+ (1,0) [0|255] ""  PC,MBMU
 SG_ S2A_SUMDATA5_CUS_Reserve7_17 : 48|8@1+ (1,0) [0|255] ""  PC,MBMU
 SG_ S2A_SUMDATA5_CUS_Reserve8_17 : 56|8@1+ (1,0) [0|255] ""  PC,MBMU

BO_ 2339766098 S2A_SUMDATA5_CUS__18: 8 SBMU
 SG_ S2A_SUMDATA5_CUS_Reserve1_18 : 0|8@1+ (1,0) [0|255] ""  PC,MBMU
 SG_ S2A_SUMDATA5_CUS_Reserve2_18 : 8|8@1+ (1,0) [0|255] ""  PC,MBMU
 SG_ S2A_SUMDATA5_CUS_Reserve3_18 : 16|8@1+ (1,0) [0|255] ""  PC,MBMU
 SG_ S2A_SUMDATA5_CUS_Reserve4_18 : 24|8@1+ (1,0) [0|255] ""  PC,MBMU
 SG_ S2A_SUMDATA5_CUS_Reserve5_18 : 32|8@1+ (1,0) [0|255] ""  PC,MBMU
 SG_ S2A_SUMDATA5_CUS_Reserve6_18 : 40|8@1+ (1,0) [0|255] ""  PC,MBMU
 SG_ S2A_SUMDATA5_CUS_Reserve7_18 : 48|8@1+ (1,0) [0|255] ""  PC,MBMU
 SG_ S2A_SUMDATA5_CUS_Reserve8_18 : 56|8@1+ (1,0) [0|255] ""  PC,MBMU

BO_ 2339766099 S2A_SUMDATA5_CUS__19: 8 SBMU
 SG_ S2A_SUMDATA5_CUS_Reserve1_19 : 0|8@1+ (1,0) [0|255] ""  PC,MBMU
 SG_ S2A_SUMDATA5_CUS_Reserve2_19 : 8|8@1+ (1,0) [0|255] ""  PC,MBMU
 SG_ S2A_SUMDATA5_CUS_Reserve3_19 : 16|8@1+ (1,0) [0|255] ""  PC,MBMU
 SG_ S2A_SUMDATA5_CUS_Reserve4_19 : 24|8@1+ (1,0) [0|255] ""  PC,MBMU
 SG_ S2A_SUMDATA5_CUS_Reserve5_19 : 32|8@1+ (1,0) [0|255] ""  PC,MBMU
 SG_ S2A_SUMDATA5_CUS_Reserve6_19 : 40|8@1+ (1,0) [0|255] ""  PC,MBMU
 SG_ S2A_SUMDATA5_CUS_Reserve7_19 : 48|8@1+ (1,0) [0|255] ""  PC,MBMU
 SG_ S2A_SUMDATA5_CUS_Reserve8_19 : 56|8@1+ (1,0) [0|255] ""  PC,MBMU

BO_ 2339766100 S2A_SUMDATA5_CUS__20: 8 SBMU
 SG_ S2A_SUMDATA5_CUS_Reserve1_20 : 0|8@1+ (1,0) [0|255] ""  PC,MBMU
 SG_ S2A_SUMDATA5_CUS_Reserve2_20 : 8|8@1+ (1,0) [0|255] ""  PC,MBMU
 SG_ S2A_SUMDATA5_CUS_Reserve3_20 : 16|8@1+ (1,0) [0|255] ""  PC,MBMU
 SG_ S2A_SUMDATA5_CUS_Reserve4_20 : 24|8@1+ (1,0) [0|255] ""  PC,MBMU
 SG_ S2A_SUMDATA5_CUS_Reserve5_20 : 32|8@1+ (1,0) [0|255] ""  PC,MBMU
 SG_ S2A_SUMDATA5_CUS_Reserve6_20 : 40|8@1+ (1,0) [0|255] ""  PC,MBMU
 SG_ S2A_SUMDATA5_CUS_Reserve7_20 : 48|8@1+ (1,0) [0|255] ""  PC,MBMU
 SG_ S2A_SUMDATA5_CUS_Reserve8_20 : 56|8@1+ (1,0) [0|255] ""  PC,MBMU

BO_ 2339766101 S2A_SUMDATA5_CUS__21: 8 SBMU
 SG_ S2A_SUMDATA5_CUS_Reserve1_21 : 0|8@1+ (1,0) [0|255] ""  PC,MBMU
 SG_ S2A_SUMDATA5_CUS_Reserve2_21 : 8|8@1+ (1,0) [0|255] ""  PC,MBMU
 SG_ S2A_SUMDATA5_CUS_Reserve3_21 : 16|8@1+ (1,0) [0|255] ""  PC,MBMU
 SG_ S2A_SUMDATA5_CUS_Reserve4_21 : 24|8@1+ (1,0) [0|255] ""  PC,MBMU
 SG_ S2A_SUMDATA5_CUS_Reserve5_21 : 32|8@1+ (1,0) [0|255] ""  PC,MBMU
 SG_ S2A_SUMDATA5_CUS_Reserve6_21 : 40|8@1+ (1,0) [0|255] ""  PC,MBMU
 SG_ S2A_SUMDATA5_CUS_Reserve7_21 : 48|8@1+ (1,0) [0|255] ""  PC,MBMU
 SG_ S2A_SUMDATA5_CUS_Reserve8_21 : 56|8@1+ (1,0) [0|255] ""  PC,MBMU

BO_ 2339766102 S2A_SUMDATA5_CUS__22: 8 SBMU
 SG_ S2A_SUMDATA5_CUS_Reserve1_22 : 0|8@1+ (1,0) [0|255] ""  PC,MBMU
 SG_ S2A_SUMDATA5_CUS_Reserve2_22 : 8|8@1+ (1,0) [0|255] ""  PC,MBMU
 SG_ S2A_SUMDATA5_CUS_Reserve3_22 : 16|8@1+ (1,0) [0|255] ""  PC,MBMU
 SG_ S2A_SUMDATA5_CUS_Reserve4_22 : 24|8@1+ (1,0) [0|255] ""  PC,MBMU
 SG_ S2A_SUMDATA5_CUS_Reserve5_22 : 32|8@1+ (1,0) [0|255] ""  PC,MBMU
 SG_ S2A_SUMDATA5_CUS_Reserve6_22 : 40|8@1+ (1,0) [0|255] ""  PC,MBMU
 SG_ S2A_SUMDATA5_CUS_Reserve7_22 : 48|8@1+ (1,0) [0|255] ""  PC,MBMU
 SG_ S2A_SUMDATA5_CUS_Reserve8_22 : 56|8@1+ (1,0) [0|255] ""  PC,MBMU

BO_ 2339766103 S2A_SUMDATA5_CUS__23: 8 SBMU
 SG_ S2A_SUMDATA5_CUS_Reserve1_23 : 0|8@1+ (1,0) [0|255] ""  PC,MBMU
 SG_ S2A_SUMDATA5_CUS_Reserve2_23 : 8|8@1+ (1,0) [0|255] ""  PC,MBMU
 SG_ S2A_SUMDATA5_CUS_Reserve3_23 : 16|8@1+ (1,0) [0|255] ""  PC,MBMU
 SG_ S2A_SUMDATA5_CUS_Reserve4_23 : 24|8@1+ (1,0) [0|255] ""  PC,MBMU
 SG_ S2A_SUMDATA5_CUS_Reserve5_23 : 32|8@1+ (1,0) [0|255] ""  PC,MBMU
 SG_ S2A_SUMDATA5_CUS_Reserve6_23 : 40|8@1+ (1,0) [0|255] ""  PC,MBMU
 SG_ S2A_SUMDATA5_CUS_Reserve7_23 : 48|8@1+ (1,0) [0|255] ""  PC,MBMU
 SG_ S2A_SUMDATA5_CUS_Reserve8_23 : 56|8@1+ (1,0) [0|255] ""  PC,MBMU

BO_ 2339766104 S2A_SUMDATA5_CUS__24: 8 SBMU
 SG_ S2A_SUMDATA5_CUS_Reserve1_24 : 0|8@1+ (1,0) [0|255] ""  PC,MBMU
 SG_ S2A_SUMDATA5_CUS_Reserve2_24 : 8|8@1+ (1,0) [0|255] ""  PC,MBMU
 SG_ S2A_SUMDATA5_CUS_Reserve3_24 : 16|8@1+ (1,0) [0|255] ""  PC,MBMU
 SG_ S2A_SUMDATA5_CUS_Reserve4_24 : 24|8@1+ (1,0) [0|255] ""  PC,MBMU
 SG_ S2A_SUMDATA5_CUS_Reserve5_24 : 32|8@1+ (1,0) [0|255] ""  PC,MBMU
 SG_ S2A_SUMDATA5_CUS_Reserve6_24 : 40|8@1+ (1,0) [0|255] ""  PC,MBMU
 SG_ S2A_SUMDATA5_CUS_Reserve7_24 : 48|8@1+ (1,0) [0|255] ""  PC,MBMU
 SG_ S2A_SUMDATA5_CUS_Reserve8_24 : 56|8@1+ (1,0) [0|255] ""  PC,MBMU

BO_ 2339766105 S2A_SUMDATA5_CUS__25: 8 SBMU
 SG_ S2A_SUMDATA5_CUS_Reserve1_25 : 0|8@1+ (1,0) [0|255] ""  PC,MBMU
 SG_ S2A_SUMDATA5_CUS_Reserve2_25 : 8|8@1+ (1,0) [0|255] ""  PC,MBMU
 SG_ S2A_SUMDATA5_CUS_Reserve3_25 : 16|8@1+ (1,0) [0|255] ""  PC,MBMU
 SG_ S2A_SUMDATA5_CUS_Reserve4_25 : 24|8@1+ (1,0) [0|255] ""  PC,MBMU
 SG_ S2A_SUMDATA5_CUS_Reserve5_25 : 32|8@1+ (1,0) [0|255] ""  PC,MBMU
 SG_ S2A_SUMDATA5_CUS_Reserve6_25 : 40|8@1+ (1,0) [0|255] ""  PC,MBMU
 SG_ S2A_SUMDATA5_CUS_Reserve7_25 : 48|8@1+ (1,0) [0|255] ""  PC,MBMU
 SG_ S2A_SUMDATA5_CUS_Reserve8_25 : 56|8@1+ (1,0) [0|255] ""  PC,MBMU

BO_ 2339766106 S2A_SUMDATA5_CUS__26: 8 SBMU
 SG_ S2A_SUMDATA5_CUS_Reserve1_26 : 0|8@1+ (1,0) [0|255] ""  PC,MBMU
 SG_ S2A_SUMDATA5_CUS_Reserve2_26 : 8|8@1+ (1,0) [0|255] ""  PC,MBMU
 SG_ S2A_SUMDATA5_CUS_Reserve3_26 : 16|8@1+ (1,0) [0|255] ""  PC,MBMU
 SG_ S2A_SUMDATA5_CUS_Reserve4_26 : 24|8@1+ (1,0) [0|255] ""  PC,MBMU
 SG_ S2A_SUMDATA5_CUS_Reserve5_26 : 32|8@1+ (1,0) [0|255] ""  PC,MBMU
 SG_ S2A_SUMDATA5_CUS_Reserve6_26 : 40|8@1+ (1,0) [0|255] ""  PC,MBMU
 SG_ S2A_SUMDATA5_CUS_Reserve7_26 : 48|8@1+ (1,0) [0|255] ""  PC,MBMU
 SG_ S2A_SUMDATA5_CUS_Reserve8_26 : 56|8@1+ (1,0) [0|255] ""  PC,MBMU

BO_ 2339766107 S2A_SUMDATA5_CUS__27: 8 SBMU
 SG_ S2A_SUMDATA5_CUS_Reserve1_27 : 0|8@1+ (1,0) [0|255] ""  PC,MBMU
 SG_ S2A_SUMDATA5_CUS_Reserve2_27 : 8|8@1+ (1,0) [0|255] ""  PC,MBMU
 SG_ S2A_SUMDATA5_CUS_Reserve3_27 : 16|8@1+ (1,0) [0|255] ""  PC,MBMU
 SG_ S2A_SUMDATA5_CUS_Reserve4_27 : 24|8@1+ (1,0) [0|255] ""  PC,MBMU
 SG_ S2A_SUMDATA5_CUS_Reserve5_27 : 32|8@1+ (1,0) [0|255] ""  PC,MBMU
 SG_ S2A_SUMDATA5_CUS_Reserve6_27 : 40|8@1+ (1,0) [0|255] ""  PC,MBMU
 SG_ S2A_SUMDATA5_CUS_Reserve7_27 : 48|8@1+ (1,0) [0|255] ""  PC,MBMU
 SG_ S2A_SUMDATA5_CUS_Reserve8_27 : 56|8@1+ (1,0) [0|255] ""  PC,MBMU

BO_ 2339766108 S2A_SUMDATA5_CUS__28: 8 SBMU
 SG_ S2A_SUMDATA5_CUS_Reserve1_28 : 0|8@1+ (1,0) [0|255] ""  PC,MBMU
 SG_ S2A_SUMDATA5_CUS_Reserve2_28 : 8|8@1+ (1,0) [0|255] ""  PC,MBMU
 SG_ S2A_SUMDATA5_CUS_Reserve3_28 : 16|8@1+ (1,0) [0|255] ""  PC,MBMU
 SG_ S2A_SUMDATA5_CUS_Reserve4_28 : 24|8@1+ (1,0) [0|255] ""  PC,MBMU
 SG_ S2A_SUMDATA5_CUS_Reserve5_28 : 32|8@1+ (1,0) [0|255] ""  PC,MBMU
 SG_ S2A_SUMDATA5_CUS_Reserve6_28 : 40|8@1+ (1,0) [0|255] ""  PC,MBMU
 SG_ S2A_SUMDATA5_CUS_Reserve7_28 : 48|8@1+ (1,0) [0|255] ""  PC,MBMU
 SG_ S2A_SUMDATA5_CUS_Reserve8_28 : 56|8@1+ (1,0) [0|255] ""  PC,MBMU

BO_ 2339766109 S2A_SUMDATA5_CUS__29: 8 SBMU
 SG_ S2A_SUMDATA5_CUS_Reserve1_29 : 0|8@1+ (1,0) [0|255] ""  PC,MBMU
 SG_ S2A_SUMDATA5_CUS_Reserve2_29 : 8|8@1+ (1,0) [0|255] ""  PC,MBMU
 SG_ S2A_SUMDATA5_CUS_Reserve3_29 : 16|8@1+ (1,0) [0|255] ""  PC,MBMU
 SG_ S2A_SUMDATA5_CUS_Reserve4_29 : 24|8@1+ (1,0) [0|255] ""  PC,MBMU
 SG_ S2A_SUMDATA5_CUS_Reserve5_29 : 32|8@1+ (1,0) [0|255] ""  PC,MBMU
 SG_ S2A_SUMDATA5_CUS_Reserve6_29 : 40|8@1+ (1,0) [0|255] ""  PC,MBMU
 SG_ S2A_SUMDATA5_CUS_Reserve7_29 : 48|8@1+ (1,0) [0|255] ""  PC,MBMU
 SG_ S2A_SUMDATA5_CUS_Reserve8_29 : 56|8@1+ (1,0) [0|255] ""  PC,MBMU

BO_ 2339766110 S2A_SUMDATA5_CUS__30: 8 SBMU
 SG_ S2A_SUMDATA5_CUS_Reserve1_30 : 0|8@1+ (1,0) [0|255] ""  PC,MBMU
 SG_ S2A_SUMDATA5_CUS_Reserve2_30 : 8|8@1+ (1,0) [0|255] ""  PC,MBMU
 SG_ S2A_SUMDATA5_CUS_Reserve3_30 : 16|8@1+ (1,0) [0|255] ""  PC,MBMU
 SG_ S2A_SUMDATA5_CUS_Reserve4_30 : 24|8@1+ (1,0) [0|255] ""  PC,MBMU
 SG_ S2A_SUMDATA5_CUS_Reserve5_30 : 32|8@1+ (1,0) [0|255] ""  PC,MBMU
 SG_ S2A_SUMDATA5_CUS_Reserve6_30 : 40|8@1+ (1,0) [0|255] ""  PC,MBMU
 SG_ S2A_SUMDATA5_CUS_Reserve7_30 : 48|8@1+ (1,0) [0|255] ""  PC,MBMU
 SG_ S2A_SUMDATA5_CUS_Reserve8_30 : 56|8@1+ (1,0) [0|255] ""  PC,MBMU

BO_ 2339766111 S2A_SUMDATA5_CUS__31: 8 SBMU
 SG_ S2A_SUMDATA5_CUS_Reserve1_31 : 0|8@1+ (1,0) [0|255] ""  PC,MBMU
 SG_ S2A_SUMDATA5_CUS_Reserve2_31 : 8|8@1+ (1,0) [0|255] ""  PC,MBMU
 SG_ S2A_SUMDATA5_CUS_Reserve3_31 : 16|8@1+ (1,0) [0|255] ""  PC,MBMU
 SG_ S2A_SUMDATA5_CUS_Reserve4_31 : 24|8@1+ (1,0) [0|255] ""  PC,MBMU
 SG_ S2A_SUMDATA5_CUS_Reserve5_31 : 32|8@1+ (1,0) [0|255] ""  PC,MBMU
 SG_ S2A_SUMDATA5_CUS_Reserve6_31 : 40|8@1+ (1,0) [0|255] ""  PC,MBMU
 SG_ S2A_SUMDATA5_CUS_Reserve7_31 : 48|8@1+ (1,0) [0|255] ""  PC,MBMU
 SG_ S2A_SUMDATA5_CUS_Reserve8_31 : 56|8@1+ (1,0) [0|255] ""  PC,MBMU

BO_ 2339766112 S2A_SUMDATA5_CUS__32: 8 SBMU
 SG_ S2A_SUMDATA5_CUS_Reserve1_32 : 0|8@1+ (1,0) [0|255] ""  PC,MBMU
 SG_ S2A_SUMDATA5_CUS_Reserve2_32 : 8|8@1+ (1,0) [0|255] ""  PC,MBMU
 SG_ S2A_SUMDATA5_CUS_Reserve3_32 : 16|8@1+ (1,0) [0|255] ""  PC,MBMU
 SG_ S2A_SUMDATA5_CUS_Reserve4_32 : 24|8@1+ (1,0) [0|255] ""  PC,MBMU
 SG_ S2A_SUMDATA5_CUS_Reserve5_32 : 32|8@1+ (1,0) [0|255] ""  PC,MBMU
 SG_ S2A_SUMDATA5_CUS_Reserve6_32 : 40|8@1+ (1,0) [0|255] ""  PC,MBMU
 SG_ S2A_SUMDATA5_CUS_Reserve7_32 : 48|8@1+ (1,0) [0|255] ""  PC,MBMU
 SG_ S2A_SUMDATA5_CUS_Reserve8_32 : 56|8@1+ (1,0) [0|255] ""  PC,MBMU

BO_ 2339766113 S2A_SUMDATA5_CUS__33: 8 SBMU
 SG_ S2A_SUMDATA5_CUS_Reserve1_33 : 0|8@1+ (1,0) [0|255] ""  PC,MBMU
 SG_ S2A_SUMDATA5_CUS_Reserve2_33 : 8|8@1+ (1,0) [0|255] ""  PC,MBMU
 SG_ S2A_SUMDATA5_CUS_Reserve3_33 : 16|8@1+ (1,0) [0|255] ""  PC,MBMU
 SG_ S2A_SUMDATA5_CUS_Reserve4_33 : 24|8@1+ (1,0) [0|255] ""  PC,MBMU
 SG_ S2A_SUMDATA5_CUS_Reserve5_33 : 32|8@1+ (1,0) [0|255] ""  PC,MBMU
 SG_ S2A_SUMDATA5_CUS_Reserve6_33 : 40|8@1+ (1,0) [0|255] ""  PC,MBMU
 SG_ S2A_SUMDATA5_CUS_Reserve7_33 : 48|8@1+ (1,0) [0|255] ""  PC,MBMU
 SG_ S2A_SUMDATA5_CUS_Reserve8_33 : 56|8@1+ (1,0) [0|255] ""  PC,MBMU

BO_ 2339766114 S2A_SUMDATA5_CUS__34: 8 SBMU
 SG_ S2A_SUMDATA5_CUS_Reserve1_34 : 0|8@1+ (1,0) [0|255] ""  PC,MBMU
 SG_ S2A_SUMDATA5_CUS_Reserve2_34 : 8|8@1+ (1,0) [0|255] ""  PC,MBMU
 SG_ S2A_SUMDATA5_CUS_Reserve3_34 : 16|8@1+ (1,0) [0|255] ""  PC,MBMU
 SG_ S2A_SUMDATA5_CUS_Reserve4_34 : 24|8@1+ (1,0) [0|255] ""  PC,MBMU
 SG_ S2A_SUMDATA5_CUS_Reserve5_34 : 32|8@1+ (1,0) [0|255] ""  PC,MBMU
 SG_ S2A_SUMDATA5_CUS_Reserve6_34 : 40|8@1+ (1,0) [0|255] ""  PC,MBMU
 SG_ S2A_SUMDATA5_CUS_Reserve7_34 : 48|8@1+ (1,0) [0|255] ""  PC,MBMU
 SG_ S2A_SUMDATA5_CUS_Reserve8_34 : 56|8@1+ (1,0) [0|255] ""  PC,MBMU

BO_ 2339766115 S2A_SUMDATA5_CUS__35: 8 SBMU
 SG_ S2A_SUMDATA5_CUS_Reserve1_35 : 0|8@1+ (1,0) [0|255] ""  PC,MBMU
 SG_ S2A_SUMDATA5_CUS_Reserve2_35 : 8|8@1+ (1,0) [0|255] ""  PC,MBMU
 SG_ S2A_SUMDATA5_CUS_Reserve3_35 : 16|8@1+ (1,0) [0|255] ""  PC,MBMU
 SG_ S2A_SUMDATA5_CUS_Reserve4_35 : 24|8@1+ (1,0) [0|255] ""  PC,MBMU
 SG_ S2A_SUMDATA5_CUS_Reserve5_35 : 32|8@1+ (1,0) [0|255] ""  PC,MBMU
 SG_ S2A_SUMDATA5_CUS_Reserve6_35 : 40|8@1+ (1,0) [0|255] ""  PC,MBMU
 SG_ S2A_SUMDATA5_CUS_Reserve7_35 : 48|8@1+ (1,0) [0|255] ""  PC,MBMU
 SG_ S2A_SUMDATA5_CUS_Reserve8_35 : 56|8@1+ (1,0) [0|255] ""  PC,MBMU

BO_ 2339766116 S2A_SUMDATA5_CUS__36: 8 SBMU
 SG_ S2A_SUMDATA5_CUS_Reserve1_36 : 0|8@1+ (1,0) [0|255] ""  PC,MBMU
 SG_ S2A_SUMDATA5_CUS_Reserve2_36 : 8|8@1+ (1,0) [0|255] ""  PC,MBMU
 SG_ S2A_SUMDATA5_CUS_Reserve3_36 : 16|8@1+ (1,0) [0|255] ""  PC,MBMU
 SG_ S2A_SUMDATA5_CUS_Reserve4_36 : 24|8@1+ (1,0) [0|255] ""  PC,MBMU
 SG_ S2A_SUMDATA5_CUS_Reserve5_36 : 32|8@1+ (1,0) [0|255] ""  PC,MBMU
 SG_ S2A_SUMDATA5_CUS_Reserve6_36 : 40|8@1+ (1,0) [0|255] ""  PC,MBMU
 SG_ S2A_SUMDATA5_CUS_Reserve7_36 : 48|8@1+ (1,0) [0|255] ""  PC,MBMU
 SG_ S2A_SUMDATA5_CUS_Reserve8_36 : 56|8@1+ (1,0) [0|255] ""  PC,MBMU

BO_ 2339766117 S2A_SUMDATA5_CUS__37: 8 SBMU
 SG_ S2A_SUMDATA5_CUS_Reserve1_37 : 0|8@1+ (1,0) [0|255] ""  PC,MBMU
 SG_ S2A_SUMDATA5_CUS_Reserve2_37 : 8|8@1+ (1,0) [0|255] ""  PC,MBMU
 SG_ S2A_SUMDATA5_CUS_Reserve3_37 : 16|8@1+ (1,0) [0|255] ""  PC,MBMU
 SG_ S2A_SUMDATA5_CUS_Reserve4_37 : 24|8@1+ (1,0) [0|255] ""  PC,MBMU
 SG_ S2A_SUMDATA5_CUS_Reserve5_37 : 32|8@1+ (1,0) [0|255] ""  PC,MBMU
 SG_ S2A_SUMDATA5_CUS_Reserve6_37 : 40|8@1+ (1,0) [0|255] ""  PC,MBMU
 SG_ S2A_SUMDATA5_CUS_Reserve7_37 : 48|8@1+ (1,0) [0|255] ""  PC,MBMU
 SG_ S2A_SUMDATA5_CUS_Reserve8_37 : 56|8@1+ (1,0) [0|255] ""  PC,MBMU

BO_ 2339766118 S2A_SUMDATA5_CUS__38: 8 SBMU
 SG_ S2A_SUMDATA5_CUS_Reserve1_38 : 0|8@1+ (1,0) [0|255] ""  PC,MBMU
 SG_ S2A_SUMDATA5_CUS_Reserve2_38 : 8|8@1+ (1,0) [0|255] ""  PC,MBMU
 SG_ S2A_SUMDATA5_CUS_Reserve3_38 : 16|8@1+ (1,0) [0|255] ""  PC,MBMU
 SG_ S2A_SUMDATA5_CUS_Reserve4_38 : 24|8@1+ (1,0) [0|255] ""  PC,MBMU
 SG_ S2A_SUMDATA5_CUS_Reserve5_38 : 32|8@1+ (1,0) [0|255] ""  PC,MBMU
 SG_ S2A_SUMDATA5_CUS_Reserve6_38 : 40|8@1+ (1,0) [0|255] ""  PC,MBMU
 SG_ S2A_SUMDATA5_CUS_Reserve7_38 : 48|8@1+ (1,0) [0|255] ""  PC,MBMU
 SG_ S2A_SUMDATA5_CUS_Reserve8_38 : 56|8@1+ (1,0) [0|255] ""  PC,MBMU

BO_ 2339766119 S2A_SUMDATA5_CUS__39: 8 SBMU
 SG_ S2A_SUMDATA5_CUS_Reserve1_39 : 0|8@1+ (1,0) [0|255] ""  PC,MBMU
 SG_ S2A_SUMDATA5_CUS_Reserve2_39 : 8|8@1+ (1,0) [0|255] ""  PC,MBMU
 SG_ S2A_SUMDATA5_CUS_Reserve3_39 : 16|8@1+ (1,0) [0|255] ""  PC,MBMU
 SG_ S2A_SUMDATA5_CUS_Reserve4_39 : 24|8@1+ (1,0) [0|255] ""  PC,MBMU
 SG_ S2A_SUMDATA5_CUS_Reserve5_39 : 32|8@1+ (1,0) [0|255] ""  PC,MBMU
 SG_ S2A_SUMDATA5_CUS_Reserve6_39 : 40|8@1+ (1,0) [0|255] ""  PC,MBMU
 SG_ S2A_SUMDATA5_CUS_Reserve7_39 : 48|8@1+ (1,0) [0|255] ""  PC,MBMU
 SG_ S2A_SUMDATA5_CUS_Reserve8_39 : 56|8@1+ (1,0) [0|255] ""  PC,MBMU

BO_ 2339766120 S2A_SUMDATA5_CUS__40: 8 SBMU
 SG_ S2A_SUMDATA5_CUS_Reserve1_40 : 0|8@1+ (1,0) [0|255] ""  PC,MBMU
 SG_ S2A_SUMDATA5_CUS_Reserve2_40 : 8|8@1+ (1,0) [0|255] ""  PC,MBMU
 SG_ S2A_SUMDATA5_CUS_Reserve3_40 : 16|8@1+ (1,0) [0|255] ""  PC,MBMU
 SG_ S2A_SUMDATA5_CUS_Reserve4_40 : 24|8@1+ (1,0) [0|255] ""  PC,MBMU
 SG_ S2A_SUMDATA5_CUS_Reserve5_40 : 32|8@1+ (1,0) [0|255] ""  PC,MBMU
 SG_ S2A_SUMDATA5_CUS_Reserve6_40 : 40|8@1+ (1,0) [0|255] ""  PC,MBMU
 SG_ S2A_SUMDATA5_CUS_Reserve7_40 : 48|8@1+ (1,0) [0|255] ""  PC,MBMU
 SG_ S2A_SUMDATA5_CUS_Reserve8_40 : 56|8@1+ (1,0) [0|255] ""  PC,MBMU

BO_ 2339766121 S2A_SUMDATA5_CUS__41: 8 SBMU
 SG_ S2A_SUMDATA5_CUS_Reserve1_41 : 0|8@1+ (1,0) [0|255] ""  PC,MBMU
 SG_ S2A_SUMDATA5_CUS_Reserve2_41 : 8|8@1+ (1,0) [0|255] ""  PC,MBMU
 SG_ S2A_SUMDATA5_CUS_Reserve3_41 : 16|8@1+ (1,0) [0|255] ""  PC,MBMU
 SG_ S2A_SUMDATA5_CUS_Reserve4_41 : 24|8@1+ (1,0) [0|255] ""  PC,MBMU
 SG_ S2A_SUMDATA5_CUS_Reserve5_41 : 32|8@1+ (1,0) [0|255] ""  PC,MBMU
 SG_ S2A_SUMDATA5_CUS_Reserve6_41 : 40|8@1+ (1,0) [0|255] ""  PC,MBMU
 SG_ S2A_SUMDATA5_CUS_Reserve7_41 : 48|8@1+ (1,0) [0|255] ""  PC,MBMU
 SG_ S2A_SUMDATA5_CUS_Reserve8_41 : 56|8@1+ (1,0) [0|255] ""  PC,MBMU

BO_ 2339766122 S2A_SUMDATA5_CUS__42: 8 SBMU
 SG_ S2A_SUMDATA5_CUS_Reserve1_42 : 0|8@1+ (1,0) [0|255] ""  PC,MBMU
 SG_ S2A_SUMDATA5_CUS_Reserve2_42 : 8|8@1+ (1,0) [0|255] ""  PC,MBMU
 SG_ S2A_SUMDATA5_CUS_Reserve3_42 : 16|8@1+ (1,0) [0|255] ""  PC,MBMU
 SG_ S2A_SUMDATA5_CUS_Reserve4_42 : 24|8@1+ (1,0) [0|255] ""  PC,MBMU
 SG_ S2A_SUMDATA5_CUS_Reserve5_42 : 32|8@1+ (1,0) [0|255] ""  PC,MBMU
 SG_ S2A_SUMDATA5_CUS_Reserve6_42 : 40|8@1+ (1,0) [0|255] ""  PC,MBMU
 SG_ S2A_SUMDATA5_CUS_Reserve7_42 : 48|8@1+ (1,0) [0|255] ""  PC,MBMU
 SG_ S2A_SUMDATA5_CUS_Reserve8_42 : 56|8@1+ (1,0) [0|255] ""  PC,MBMU

BO_ 2339766123 S2A_SUMDATA5_CUS__43: 8 SBMU
 SG_ S2A_SUMDATA5_CUS_Reserve1_43 : 0|8@1+ (1,0) [0|255] ""  PC,MBMU
 SG_ S2A_SUMDATA5_CUS_Reserve2_43 : 8|8@1+ (1,0) [0|255] ""  PC,MBMU
 SG_ S2A_SUMDATA5_CUS_Reserve3_43 : 16|8@1+ (1,0) [0|255] ""  PC,MBMU
 SG_ S2A_SUMDATA5_CUS_Reserve4_43 : 24|8@1+ (1,0) [0|255] ""  PC,MBMU
 SG_ S2A_SUMDATA5_CUS_Reserve5_43 : 32|8@1+ (1,0) [0|255] ""  PC,MBMU
 SG_ S2A_SUMDATA5_CUS_Reserve6_43 : 40|8@1+ (1,0) [0|255] ""  PC,MBMU
 SG_ S2A_SUMDATA5_CUS_Reserve7_43 : 48|8@1+ (1,0) [0|255] ""  PC,MBMU
 SG_ S2A_SUMDATA5_CUS_Reserve8_43 : 56|8@1+ (1,0) [0|255] ""  PC,MBMU

BO_ 2339766124 S2A_SUMDATA5_CUS__44: 8 SBMU
 SG_ S2A_SUMDATA5_CUS_Reserve1_44 : 0|8@1+ (1,0) [0|255] ""  PC,MBMU
 SG_ S2A_SUMDATA5_CUS_Reserve2_44 : 8|8@1+ (1,0) [0|255] ""  PC,MBMU
 SG_ S2A_SUMDATA5_CUS_Reserve3_44 : 16|8@1+ (1,0) [0|255] ""  PC,MBMU
 SG_ S2A_SUMDATA5_CUS_Reserve4_44 : 24|8@1+ (1,0) [0|255] ""  PC,MBMU
 SG_ S2A_SUMDATA5_CUS_Reserve5_44 : 32|8@1+ (1,0) [0|255] ""  PC,MBMU
 SG_ S2A_SUMDATA5_CUS_Reserve6_44 : 40|8@1+ (1,0) [0|255] ""  PC,MBMU
 SG_ S2A_SUMDATA5_CUS_Reserve7_44 : 48|8@1+ (1,0) [0|255] ""  PC,MBMU
 SG_ S2A_SUMDATA5_CUS_Reserve8_44 : 56|8@1+ (1,0) [0|255] ""  PC,MBMU

BO_ 2339766125 S2A_SUMDATA5_CUS__45: 8 SBMU
 SG_ S2A_SUMDATA5_CUS_Reserve1_45 : 0|8@1+ (1,0) [0|255] ""  PC,MBMU
 SG_ S2A_SUMDATA5_CUS_Reserve2_45 : 8|8@1+ (1,0) [0|255] ""  PC,MBMU
 SG_ S2A_SUMDATA5_CUS_Reserve3_45 : 16|8@1+ (1,0) [0|255] ""  PC,MBMU
 SG_ S2A_SUMDATA5_CUS_Reserve4_45 : 24|8@1+ (1,0) [0|255] ""  PC,MBMU
 SG_ S2A_SUMDATA5_CUS_Reserve5_45 : 32|8@1+ (1,0) [0|255] ""  PC,MBMU
 SG_ S2A_SUMDATA5_CUS_Reserve6_45 : 40|8@1+ (1,0) [0|255] ""  PC,MBMU
 SG_ S2A_SUMDATA5_CUS_Reserve7_45 : 48|8@1+ (1,0) [0|255] ""  PC,MBMU
 SG_ S2A_SUMDATA5_CUS_Reserve8_45 : 56|8@1+ (1,0) [0|255] ""  PC,MBMU

BO_ 2339766126 S2A_SUMDATA5_CUS__46: 8 SBMU
 SG_ S2A_SUMDATA5_CUS_Reserve1_46 : 0|8@1+ (1,0) [0|255] ""  PC,MBMU
 SG_ S2A_SUMDATA5_CUS_Reserve2_46 : 8|8@1+ (1,0) [0|255] ""  PC,MBMU
 SG_ S2A_SUMDATA5_CUS_Reserve3_46 : 16|8@1+ (1,0) [0|255] ""  PC,MBMU
 SG_ S2A_SUMDATA5_CUS_Reserve4_46 : 24|8@1+ (1,0) [0|255] ""  PC,MBMU
 SG_ S2A_SUMDATA5_CUS_Reserve5_46 : 32|8@1+ (1,0) [0|255] ""  PC,MBMU
 SG_ S2A_SUMDATA5_CUS_Reserve6_46 : 40|8@1+ (1,0) [0|255] ""  PC,MBMU
 SG_ S2A_SUMDATA5_CUS_Reserve7_46 : 48|8@1+ (1,0) [0|255] ""  PC,MBMU
 SG_ S2A_SUMDATA5_CUS_Reserve8_46 : 56|8@1+ (1,0) [0|255] ""  PC,MBMU

BO_ 2339766127 S2A_SUMDATA5_CUS__47: 8 SBMU
 SG_ S2A_SUMDATA5_CUS_Reserve1_47 : 0|8@1+ (1,0) [0|255] ""  PC,MBMU
 SG_ S2A_SUMDATA5_CUS_Reserve2_47 : 8|8@1+ (1,0) [0|255] ""  PC,MBMU
 SG_ S2A_SUMDATA5_CUS_Reserve3_47 : 16|8@1+ (1,0) [0|255] ""  PC,MBMU
 SG_ S2A_SUMDATA5_CUS_Reserve4_47 : 24|8@1+ (1,0) [0|255] ""  PC,MBMU
 SG_ S2A_SUMDATA5_CUS_Reserve5_47 : 32|8@1+ (1,0) [0|255] ""  PC,MBMU
 SG_ S2A_SUMDATA5_CUS_Reserve6_47 : 40|8@1+ (1,0) [0|255] ""  PC,MBMU
 SG_ S2A_SUMDATA5_CUS_Reserve7_47 : 48|8@1+ (1,0) [0|255] ""  PC,MBMU
 SG_ S2A_SUMDATA5_CUS_Reserve8_47 : 56|8@1+ (1,0) [0|255] ""  PC,MBMU

BO_ 2339766128 S2A_SUMDATA5_CUS__48: 8 SBMU
 SG_ S2A_SUMDATA5_CUS_Reserve1_48 : 0|8@1+ (1,0) [0|255] ""  PC,MBMU
 SG_ S2A_SUMDATA5_CUS_Reserve2_48 : 8|8@1+ (1,0) [0|255] ""  PC,MBMU
 SG_ S2A_SUMDATA5_CUS_Reserve3_48 : 16|8@1+ (1,0) [0|255] ""  PC,MBMU
 SG_ S2A_SUMDATA5_CUS_Reserve4_48 : 24|8@1+ (1,0) [0|255] ""  PC,MBMU
 SG_ S2A_SUMDATA5_CUS_Reserve5_48 : 32|8@1+ (1,0) [0|255] ""  PC,MBMU
 SG_ S2A_SUMDATA5_CUS_Reserve6_48 : 40|8@1+ (1,0) [0|255] ""  PC,MBMU
 SG_ S2A_SUMDATA5_CUS_Reserve7_48 : 48|8@1+ (1,0) [0|255] ""  PC,MBMU
 SG_ S2A_SUMDATA5_CUS_Reserve8_48 : 56|8@1+ (1,0) [0|255] ""  PC,MBMU

BO_ 2339766129 S2A_SUMDATA5_CUS__49: 8 SBMU
 SG_ S2A_SUMDATA5_CUS_Reserve1_49 : 0|8@1+ (1,0) [0|255] ""  PC,MBMU
 SG_ S2A_SUMDATA5_CUS_Reserve2_49 : 8|8@1+ (1,0) [0|255] ""  PC,MBMU
 SG_ S2A_SUMDATA5_CUS_Reserve3_49 : 16|8@1+ (1,0) [0|255] ""  PC,MBMU
 SG_ S2A_SUMDATA5_CUS_Reserve4_49 : 24|8@1+ (1,0) [0|255] ""  PC,MBMU
 SG_ S2A_SUMDATA5_CUS_Reserve5_49 : 32|8@1+ (1,0) [0|255] ""  PC,MBMU
 SG_ S2A_SUMDATA5_CUS_Reserve6_49 : 40|8@1+ (1,0) [0|255] ""  PC,MBMU
 SG_ S2A_SUMDATA5_CUS_Reserve7_49 : 48|8@1+ (1,0) [0|255] ""  PC,MBMU
 SG_ S2A_SUMDATA5_CUS_Reserve8_49 : 56|8@1+ (1,0) [0|255] ""  PC,MBMU

BO_ 2339766130 S2A_SUMDATA5_CUS__50: 8 SBMU
 SG_ S2A_SUMDATA5_CUS_Reserve1_50 : 0|8@1+ (1,0) [0|255] ""  PC,MBMU
 SG_ S2A_SUMDATA5_CUS_Reserve2_50 : 8|8@1+ (1,0) [0|255] ""  PC,MBMU
 SG_ S2A_SUMDATA5_CUS_Reserve3_50 : 16|8@1+ (1,0) [0|255] ""  PC,MBMU
 SG_ S2A_SUMDATA5_CUS_Reserve4_50 : 24|8@1+ (1,0) [0|255] ""  PC,MBMU
 SG_ S2A_SUMDATA5_CUS_Reserve5_50 : 32|8@1+ (1,0) [0|255] ""  PC,MBMU
 SG_ S2A_SUMDATA5_CUS_Reserve6_50 : 40|8@1+ (1,0) [0|255] ""  PC,MBMU
 SG_ S2A_SUMDATA5_CUS_Reserve7_50 : 48|8@1+ (1,0) [0|255] ""  PC,MBMU
 SG_ S2A_SUMDATA5_CUS_Reserve8_50 : 56|8@1+ (1,0) [0|255] ""  PC,MBMU

BO_ 2339766131 S2A_SUMDATA5_CUS__51: 8 SBMU
 SG_ S2A_SUMDATA5_CUS_Reserve1_51 : 0|8@1+ (1,0) [0|255] ""  PC,MBMU
 SG_ S2A_SUMDATA5_CUS_Reserve2_51 : 8|8@1+ (1,0) [0|255] ""  PC,MBMU
 SG_ S2A_SUMDATA5_CUS_Reserve3_51 : 16|8@1+ (1,0) [0|255] ""  PC,MBMU
 SG_ S2A_SUMDATA5_CUS_Reserve4_51 : 24|8@1+ (1,0) [0|255] ""  PC,MBMU
 SG_ S2A_SUMDATA5_CUS_Reserve5_51 : 32|8@1+ (1,0) [0|255] ""  PC,MBMU
 SG_ S2A_SUMDATA5_CUS_Reserve6_51 : 40|8@1+ (1,0) [0|255] ""  PC,MBMU
 SG_ S2A_SUMDATA5_CUS_Reserve7_51 : 48|8@1+ (1,0) [0|255] ""  PC,MBMU
 SG_ S2A_SUMDATA5_CUS_Reserve8_51 : 56|8@1+ (1,0) [0|255] ""  PC,MBMU

BO_ 2339766132 S2A_SUMDATA5_CUS__52: 8 SBMU
 SG_ S2A_SUMDATA5_CUS_Reserve1_52 : 0|8@1+ (1,0) [0|255] ""  PC,MBMU
 SG_ S2A_SUMDATA5_CUS_Reserve2_52 : 8|8@1+ (1,0) [0|255] ""  PC,MBMU
 SG_ S2A_SUMDATA5_CUS_Reserve3_52 : 16|8@1+ (1,0) [0|255] ""  PC,MBMU
 SG_ S2A_SUMDATA5_CUS_Reserve4_52 : 24|8@1+ (1,0) [0|255] ""  PC,MBMU
 SG_ S2A_SUMDATA5_CUS_Reserve5_52 : 32|8@1+ (1,0) [0|255] ""  PC,MBMU
 SG_ S2A_SUMDATA5_CUS_Reserve6_52 : 40|8@1+ (1,0) [0|255] ""  PC,MBMU
 SG_ S2A_SUMDATA5_CUS_Reserve7_52 : 48|8@1+ (1,0) [0|255] ""  PC,MBMU
 SG_ S2A_SUMDATA5_CUS_Reserve8_52 : 56|8@1+ (1,0) [0|255] ""  PC,MBMU

BO_ 2339766133 S2A_SUMDATA5_CUS__53: 8 SBMU
 SG_ S2A_SUMDATA5_CUS_Reserve1_53 : 0|8@1+ (1,0) [0|255] ""  PC,MBMU
 SG_ S2A_SUMDATA5_CUS_Reserve2_53 : 8|8@1+ (1,0) [0|255] ""  PC,MBMU
 SG_ S2A_SUMDATA5_CUS_Reserve3_53 : 16|8@1+ (1,0) [0|255] ""  PC,MBMU
 SG_ S2A_SUMDATA5_CUS_Reserve4_53 : 24|8@1+ (1,0) [0|255] ""  PC,MBMU
 SG_ S2A_SUMDATA5_CUS_Reserve5_53 : 32|8@1+ (1,0) [0|255] ""  PC,MBMU
 SG_ S2A_SUMDATA5_CUS_Reserve6_53 : 40|8@1+ (1,0) [0|255] ""  PC,MBMU
 SG_ S2A_SUMDATA5_CUS_Reserve7_53 : 48|8@1+ (1,0) [0|255] ""  PC,MBMU
 SG_ S2A_SUMDATA5_CUS_Reserve8_53 : 56|8@1+ (1,0) [0|255] ""  PC,MBMU

BO_ 2339766134 S2A_SUMDATA5_CUS__54: 8 SBMU
 SG_ S2A_SUMDATA5_CUS_Reserve1_54 : 0|8@1+ (1,0) [0|255] ""  PC,MBMU
 SG_ S2A_SUMDATA5_CUS_Reserve2_54 : 8|8@1+ (1,0) [0|255] ""  PC,MBMU
 SG_ S2A_SUMDATA5_CUS_Reserve3_54 : 16|8@1+ (1,0) [0|255] ""  PC,MBMU
 SG_ S2A_SUMDATA5_CUS_Reserve4_54 : 24|8@1+ (1,0) [0|255] ""  PC,MBMU
 SG_ S2A_SUMDATA5_CUS_Reserve5_54 : 32|8@1+ (1,0) [0|255] ""  PC,MBMU
 SG_ S2A_SUMDATA5_CUS_Reserve6_54 : 40|8@1+ (1,0) [0|255] ""  PC,MBMU
 SG_ S2A_SUMDATA5_CUS_Reserve7_54 : 48|8@1+ (1,0) [0|255] ""  PC,MBMU
 SG_ S2A_SUMDATA5_CUS_Reserve8_54 : 56|8@1+ (1,0) [0|255] ""  PC,MBMU

BO_ 2339766135 S2A_SUMDATA5_CUS__55: 8 SBMU
 SG_ S2A_SUMDATA5_CUS_Reserve1_55 : 0|8@1+ (1,0) [0|255] ""  PC,MBMU
 SG_ S2A_SUMDATA5_CUS_Reserve2_55 : 8|8@1+ (1,0) [0|255] ""  PC,MBMU
 SG_ S2A_SUMDATA5_CUS_Reserve3_55 : 16|8@1+ (1,0) [0|255] ""  PC,MBMU
 SG_ S2A_SUMDATA5_CUS_Reserve4_55 : 24|8@1+ (1,0) [0|255] ""  PC,MBMU
 SG_ S2A_SUMDATA5_CUS_Reserve5_55 : 32|8@1+ (1,0) [0|255] ""  PC,MBMU
 SG_ S2A_SUMDATA5_CUS_Reserve6_55 : 40|8@1+ (1,0) [0|255] ""  PC,MBMU
 SG_ S2A_SUMDATA5_CUS_Reserve7_55 : 48|8@1+ (1,0) [0|255] ""  PC,MBMU
 SG_ S2A_SUMDATA5_CUS_Reserve8_55 : 56|8@1+ (1,0) [0|255] ""  PC,MBMU

BO_ 2339766136 S2A_SUMDATA5_CUS__56: 8 SBMU
 SG_ S2A_SUMDATA5_CUS_Reserve1_56 : 0|8@1+ (1,0) [0|255] ""  PC,MBMU
 SG_ S2A_SUMDATA5_CUS_Reserve2_56 : 8|8@1+ (1,0) [0|255] ""  PC,MBMU
 SG_ S2A_SUMDATA5_CUS_Reserve3_56 : 16|8@1+ (1,0) [0|255] ""  PC,MBMU
 SG_ S2A_SUMDATA5_CUS_Reserve4_56 : 24|8@1+ (1,0) [0|255] ""  PC,MBMU
 SG_ S2A_SUMDATA5_CUS_Reserve5_56 : 32|8@1+ (1,0) [0|255] ""  PC,MBMU
 SG_ S2A_SUMDATA5_CUS_Reserve6_56 : 40|8@1+ (1,0) [0|255] ""  PC,MBMU
 SG_ S2A_SUMDATA5_CUS_Reserve7_56 : 48|8@1+ (1,0) [0|255] ""  PC,MBMU
 SG_ S2A_SUMDATA5_CUS_Reserve8_56 : 56|8@1+ (1,0) [0|255] ""  PC,MBMU

BO_ 2339766137 S2A_SUMDATA5_CUS__57: 8 SBMU
 SG_ S2A_SUMDATA5_CUS_Reserve1_57 : 0|8@1+ (1,0) [0|255] ""  PC,MBMU
 SG_ S2A_SUMDATA5_CUS_Reserve2_57 : 8|8@1+ (1,0) [0|255] ""  PC,MBMU
 SG_ S2A_SUMDATA5_CUS_Reserve3_57 : 16|8@1+ (1,0) [0|255] ""  PC,MBMU
 SG_ S2A_SUMDATA5_CUS_Reserve4_57 : 24|8@1+ (1,0) [0|255] ""  PC,MBMU
 SG_ S2A_SUMDATA5_CUS_Reserve5_57 : 32|8@1+ (1,0) [0|255] ""  PC,MBMU
 SG_ S2A_SUMDATA5_CUS_Reserve6_57 : 40|8@1+ (1,0) [0|255] ""  PC,MBMU
 SG_ S2A_SUMDATA5_CUS_Reserve7_57 : 48|8@1+ (1,0) [0|255] ""  PC,MBMU
 SG_ S2A_SUMDATA5_CUS_Reserve8_57 : 56|8@1+ (1,0) [0|255] ""  PC,MBMU

BO_ 2339766138 S2A_SUMDATA5_CUS__58: 8 SBMU
 SG_ S2A_SUMDATA5_CUS_Reserve1_58 : 0|8@1+ (1,0) [0|255] ""  PC,MBMU
 SG_ S2A_SUMDATA5_CUS_Reserve2_58 : 8|8@1+ (1,0) [0|255] ""  PC,MBMU
 SG_ S2A_SUMDATA5_CUS_Reserve3_58 : 16|8@1+ (1,0) [0|255] ""  PC,MBMU
 SG_ S2A_SUMDATA5_CUS_Reserve4_58 : 24|8@1+ (1,0) [0|255] ""  PC,MBMU
 SG_ S2A_SUMDATA5_CUS_Reserve5_58 : 32|8@1+ (1,0) [0|255] ""  PC,MBMU
 SG_ S2A_SUMDATA5_CUS_Reserve6_58 : 40|8@1+ (1,0) [0|255] ""  PC,MBMU
 SG_ S2A_SUMDATA5_CUS_Reserve7_58 : 48|8@1+ (1,0) [0|255] ""  PC,MBMU
 SG_ S2A_SUMDATA5_CUS_Reserve8_58 : 56|8@1+ (1,0) [0|255] ""  PC,MBMU

BO_ 2339766139 S2A_SUMDATA5_CUS__59: 8 SBMU
 SG_ S2A_SUMDATA5_CUS_Reserve1_59 : 0|8@1+ (1,0) [0|255] ""  PC,MBMU
 SG_ S2A_SUMDATA5_CUS_Reserve2_59 : 8|8@1+ (1,0) [0|255] ""  PC,MBMU
 SG_ S2A_SUMDATA5_CUS_Reserve3_59 : 16|8@1+ (1,0) [0|255] ""  PC,MBMU
 SG_ S2A_SUMDATA5_CUS_Reserve4_59 : 24|8@1+ (1,0) [0|255] ""  PC,MBMU
 SG_ S2A_SUMDATA5_CUS_Reserve5_59 : 32|8@1+ (1,0) [0|255] ""  PC,MBMU
 SG_ S2A_SUMDATA5_CUS_Reserve6_59 : 40|8@1+ (1,0) [0|255] ""  PC,MBMU
 SG_ S2A_SUMDATA5_CUS_Reserve7_59 : 48|8@1+ (1,0) [0|255] ""  PC,MBMU
 SG_ S2A_SUMDATA5_CUS_Reserve8_59 : 56|8@1+ (1,0) [0|255] ""  PC,MBMU

BO_ 2339766140 S2A_SUMDATA5_CUS__60: 8 SBMU
 SG_ S2A_SUMDATA5_CUS_Reserve1_60 : 0|8@1+ (1,0) [0|255] ""  PC,MBMU
 SG_ S2A_SUMDATA5_CUS_Reserve2_60 : 8|8@1+ (1,0) [0|255] ""  PC,MBMU
 SG_ S2A_SUMDATA5_CUS_Reserve3_60 : 16|8@1+ (1,0) [0|255] ""  PC,MBMU
 SG_ S2A_SUMDATA5_CUS_Reserve4_60 : 24|8@1+ (1,0) [0|255] ""  PC,MBMU
 SG_ S2A_SUMDATA5_CUS_Reserve5_60 : 32|8@1+ (1,0) [0|255] ""  PC,MBMU
 SG_ S2A_SUMDATA5_CUS_Reserve6_60 : 40|8@1+ (1,0) [0|255] ""  PC,MBMU
 SG_ S2A_SUMDATA5_CUS_Reserve7_60 : 48|8@1+ (1,0) [0|255] ""  PC,MBMU
 SG_ S2A_SUMDATA5_CUS_Reserve8_60 : 56|8@1+ (1,0) [0|255] ""  PC,MBMU

BO_ 2339766141 S2A_SUMDATA5_CUS__61: 8 SBMU
 SG_ S2A_SUMDATA5_CUS_Reserve1_61 : 0|8@1+ (1,0) [0|255] ""  PC,MBMU
 SG_ S2A_SUMDATA5_CUS_Reserve2_61 : 8|8@1+ (1,0) [0|255] ""  PC,MBMU
 SG_ S2A_SUMDATA5_CUS_Reserve3_61 : 16|8@1+ (1,0) [0|255] ""  PC,MBMU
 SG_ S2A_SUMDATA5_CUS_Reserve4_61 : 24|8@1+ (1,0) [0|255] ""  PC,MBMU
 SG_ S2A_SUMDATA5_CUS_Reserve5_61 : 32|8@1+ (1,0) [0|255] ""  PC,MBMU
 SG_ S2A_SUMDATA5_CUS_Reserve6_61 : 40|8@1+ (1,0) [0|255] ""  PC,MBMU
 SG_ S2A_SUMDATA5_CUS_Reserve7_61 : 48|8@1+ (1,0) [0|255] ""  PC,MBMU
 SG_ S2A_SUMDATA5_CUS_Reserve8_61 : 56|8@1+ (1,0) [0|255] ""  PC,MBMU

BO_ 2339766142 S2A_SUMDATA5_CUS__62: 8 SBMU
 SG_ S2A_SUMDATA5_CUS_Reserve1_62 : 0|8@1+ (1,0) [0|255] ""  PC,MBMU
 SG_ S2A_SUMDATA5_CUS_Reserve2_62 : 8|8@1+ (1,0) [0|255] ""  PC,MBMU
 SG_ S2A_SUMDATA5_CUS_Reserve3_62 : 16|8@1+ (1,0) [0|255] ""  PC,MBMU
 SG_ S2A_SUMDATA5_CUS_Reserve4_62 : 24|8@1+ (1,0) [0|255] ""  PC,MBMU
 SG_ S2A_SUMDATA5_CUS_Reserve5_62 : 32|8@1+ (1,0) [0|255] ""  PC,MBMU
 SG_ S2A_SUMDATA5_CUS_Reserve6_62 : 40|8@1+ (1,0) [0|255] ""  PC,MBMU
 SG_ S2A_SUMDATA5_CUS_Reserve7_62 : 48|8@1+ (1,0) [0|255] ""  PC,MBMU
 SG_ S2A_SUMDATA5_CUS_Reserve8_62 : 56|8@1+ (1,0) [0|255] ""  PC,MBMU

BO_ 2339766143 S2A_SUMDATA5_CUS__63: 8 SBMU
 SG_ S2A_SUMDATA5_CUS_Reserve1_63 : 0|8@1+ (1,0) [0|255] ""  PC,MBMU
 SG_ S2A_SUMDATA5_CUS_Reserve2_63 : 8|8@1+ (1,0) [0|255] ""  PC,MBMU
 SG_ S2A_SUMDATA5_CUS_Reserve3_63 : 16|8@1+ (1,0) [0|255] ""  PC,MBMU
 SG_ S2A_SUMDATA5_CUS_Reserve4_63 : 24|8@1+ (1,0) [0|255] ""  PC,MBMU
 SG_ S2A_SUMDATA5_CUS_Reserve5_63 : 32|8@1+ (1,0) [0|255] ""  PC,MBMU
 SG_ S2A_SUMDATA5_CUS_Reserve6_63 : 40|8@1+ (1,0) [0|255] ""  PC,MBMU
 SG_ S2A_SUMDATA5_CUS_Reserve7_63 : 48|8@1+ (1,0) [0|255] ""  PC,MBMU
 SG_ S2A_SUMDATA5_CUS_Reserve8_63 : 56|8@1+ (1,0) [0|255] ""  PC,MBMU

BO_ 2148749633 S2L_SUMDATA1__01: 8 SBMU
 SG_ CellHeatMode_Status : 4|1@1+ (1,0) [0|1] ""  PC,MBMU
 SG_ CellHeatMode_PermitStatus : 22|1@1+ (1,0) [0|1] ""  PC,MBMU

BO_ 2148749634 S2L_SUMDATA1__02: 8 SBMU
 SG_ CellHeatMode_Status : 4|1@1+ (1,0) [0|1] ""  PC,MBMU
 SG_ CellHeatMode_PermitStatus : 22|1@1+ (1,0) [0|1] ""  PC,MBMU

BO_ 2148749635 S2L_SUMDATA1__03: 8 SBMU
 SG_ CellHeatMode_Status : 4|1@1+ (1,0) [0|1] ""  PC,MBMU
 SG_ CellHeatMode_PermitStatus : 22|1@1+ (1,0) [0|1] ""  PC,MBMU

BO_ 2148749636 S2L_SUMDATA1__04: 8 SBMU
 SG_ CellHeatMode_Status : 4|1@1+ (1,0) [0|1] ""  PC,MBMU
 SG_ CellHeatMode_PermitStatus : 22|1@1+ (1,0) [0|1] ""  PC,MBMU

BO_ 2148749637 S2L_SUMDATA1__05: 8 SBMU
 SG_ CellHeatMode_Status : 4|1@1+ (1,0) [0|1] ""  PC,MBMU
 SG_ CellHeatMode_PermitStatus : 22|1@1+ (1,0) [0|1] ""  PC,MBMU

BO_ 2148749638 S2L_SUMDATA1__06: 8 SBMU
 SG_ CellHeatMode_Status : 4|1@1+ (1,0) [0|1] ""  PC,MBMU
 SG_ CellHeatMode_PermitStatus : 22|1@1+ (1,0) [0|1] ""  PC,MBMU

BO_ 2148749639 S2L_SUMDATA1__07: 8 SBMU
 SG_ CellHeatMode_Status : 4|1@1+ (1,0) [0|1] ""  PC,MBMU
 SG_ CellHeatMode_PermitStatus : 22|1@1+ (1,0) [0|1] ""  PC,MBMU

BO_ 2148749640 S2L_SUMDATA1__08: 8 SBMU
 SG_ CellHeatMode_Status : 4|1@1+ (1,0) [0|1] ""  PC,MBMU
 SG_ CellHeatMode_PermitStatus : 22|1@1+ (1,0) [0|1] ""  PC,MBMU

BO_ 2148749641 S2L_SUMDATA1__09: 8 SBMU
 SG_ CellHeatMode_Status : 4|1@1+ (1,0) [0|1] ""  PC,MBMU
 SG_ CellHeatMode_PermitStatus : 22|1@1+ (1,0) [0|1] ""  PC,MBMU

BO_ 2148749642 S2L_SUMDATA1__10: 8 SBMU
 SG_ CellHeatMode_Status : 4|1@1+ (1,0) [0|1] ""  PC,MBMU
 SG_ CellHeatMode_PermitStatus : 22|1@1+ (1,0) [0|1] ""  PC,MBMU

BO_ 2148749643 S2L_SUMDATA1__11: 8 SBMU
 SG_ CellHeatMode_Status : 4|1@1+ (1,0) [0|1] ""  PC,MBMU
 SG_ CellHeatMode_PermitStatus : 22|1@1+ (1,0) [0|1] ""  PC,MBMU

BO_ 2148749644 S2L_SUMDATA1__12: 8 SBMU
 SG_ CellHeatMode_Status : 4|1@1+ (1,0) [0|1] ""  PC,MBMU
 SG_ CellHeatMode_PermitStatus : 22|1@1+ (1,0) [0|1] ""  PC,MBMU

BO_ 2148749645 S2L_SUMDATA1__13: 8 SBMU
 SG_ CellHeatMode_Status : 4|1@1+ (1,0) [0|1] ""  PC,MBMU
 SG_ CellHeatMode_PermitStatus : 22|1@1+ (1,0) [0|1] ""  PC,MBMU

BO_ 2148749646 S2L_SUMDATA1__14: 8 SBMU
 SG_ CellHeatMode_Status : 4|1@1+ (1,0) [0|1] ""  PC,MBMU
 SG_ CellHeatMode_PermitStatus : 22|1@1+ (1,0) [0|1] ""  PC,MBMU

BO_ 2148749647 S2L_SUMDATA1__15: 8 SBMU
 SG_ CellHeatMode_Status : 4|1@1+ (1,0) [0|1] ""  PC,MBMU
 SG_ CellHeatMode_PermitStatus : 22|1@1+ (1,0) [0|1] ""  PC,MBMU

BO_ 2148749648 S2L_SUMDATA1__16: 8 SBMU
 SG_ CellHeatMode_Status : 4|1@1+ (1,0) [0|1] ""  PC,MBMU
 SG_ CellHeatMode_PermitStatus : 22|1@1+ (1,0) [0|1] ""  PC,MBMU

BO_ 2148749649 S2L_SUMDATA1__17: 8 SBMU
 SG_ CellHeatMode_Status : 4|1@1+ (1,0) [0|1] ""  PC,MBMU
 SG_ CellHeatMode_PermitStatus : 22|1@1+ (1,0) [0|1] ""  PC,MBMU

BO_ 2148749650 S2L_SUMDATA1__18: 8 SBMU
 SG_ CellHeatMode_Status : 4|1@1+ (1,0) [0|1] ""  PC,MBMU
 SG_ CellHeatMode_PermitStatus : 22|1@1+ (1,0) [0|1] ""  PC,MBMU

BO_ 2148749651 S2L_SUMDATA1__19: 8 SBMU
 SG_ CellHeatMode_Status : 4|1@1+ (1,0) [0|1] ""  PC,MBMU
 SG_ CellHeatMode_PermitStatus : 22|1@1+ (1,0) [0|1] ""  PC,MBMU

BO_ 2148749652 S2L_SUMDATA1__20: 8 SBMU
 SG_ CellHeatMode_Status : 4|1@1+ (1,0) [0|1] ""  PC,MBMU
 SG_ CellHeatMode_PermitStatus : 22|1@1+ (1,0) [0|1] ""  PC,MBMU

BO_ 2148749653 S2L_SUMDATA1__21: 8 SBMU
 SG_ CellHeatMode_Status : 4|1@1+ (1,0) [0|1] ""  PC,MBMU
 SG_ CellHeatMode_PermitStatus : 22|1@1+ (1,0) [0|1] ""  PC,MBMU

BO_ 2148749654 S2L_SUMDATA1__22: 8 SBMU
 SG_ CellHeatMode_Status : 4|1@1+ (1,0) [0|1] ""  PC,MBMU
 SG_ CellHeatMode_PermitStatus : 22|1@1+ (1,0) [0|1] ""  PC,MBMU

BO_ 2148749655 S2L_SUMDATA1__23: 8 SBMU
 SG_ CellHeatMode_Status : 4|1@1+ (1,0) [0|1] ""  PC,MBMU
 SG_ CellHeatMode_PermitStatus : 22|1@1+ (1,0) [0|1] ""  PC,MBMU

BO_ 2148749656 S2L_SUMDATA1__24: 8 SBMU
 SG_ CellHeatMode_Status : 4|1@1+ (1,0) [0|1] ""  PC,MBMU
 SG_ CellHeatMode_PermitStatus : 22|1@1+ (1,0) [0|1] ""  PC,MBMU

BO_ 2148749657 S2L_SUMDATA1__25: 8 SBMU
 SG_ CellHeatMode_Status : 4|1@1+ (1,0) [0|1] ""  PC,MBMU
 SG_ CellHeatMode_PermitStatus : 22|1@1+ (1,0) [0|1] ""  PC,MBMU

BO_ 2148749658 S2L_SUMDATA1__26: 8 SBMU
 SG_ CellHeatMode_Status : 4|1@1+ (1,0) [0|1] ""  PC,MBMU
 SG_ CellHeatMode_PermitStatus : 22|1@1+ (1,0) [0|1] ""  PC,MBMU

BO_ 2148749659 S2L_SUMDATA1__27: 8 SBMU
 SG_ CellHeatMode_Status : 4|1@1+ (1,0) [0|1] ""  PC,MBMU
 SG_ CellHeatMode_PermitStatus : 22|1@1+ (1,0) [0|1] ""  PC,MBMU

BO_ 2148749660 S2L_SUMDATA1__28: 8 SBMU
 SG_ CellHeatMode_Status : 4|1@1+ (1,0) [0|1] ""  PC,MBMU
 SG_ CellHeatMode_PermitStatus : 22|1@1+ (1,0) [0|1] ""  PC,MBMU

BO_ 2148749661 S2L_SUMDATA1__29: 8 SBMU
 SG_ CellHeatMode_Status : 4|1@1+ (1,0) [0|1] ""  PC,MBMU
 SG_ CellHeatMode_PermitStatus : 22|1@1+ (1,0) [0|1] ""  PC,MBMU

BO_ 2148749662 S2L_SUMDATA1__30: 8 SBMU
 SG_ CellHeatMode_Status : 4|1@1+ (1,0) [0|1] ""  PC,MBMU
 SG_ CellHeatMode_PermitStatus : 22|1@1+ (1,0) [0|1] ""  PC,MBMU

BO_ 2148749663 S2L_SUMDATA1__31: 8 SBMU
 SG_ CellHeatMode_Status : 4|1@1+ (1,0) [0|1] ""  PC,MBMU
 SG_ CellHeatMode_PermitStatus : 22|1@1+ (1,0) [0|1] ""  PC,MBMU

BO_ 2148749664 S2L_SUMDATA1__32: 8 SBMU
 SG_ CellHeatMode_Status : 4|1@1+ (1,0) [0|1] ""  PC,MBMU
 SG_ CellHeatMode_PermitStatus : 22|1@1+ (1,0) [0|1] ""  PC,MBMU

BO_ 2148749665 S2L_SUMDATA1__33: 8 SBMU
 SG_ CellHeatMode_Status : 4|1@1+ (1,0) [0|1] ""  PC,MBMU
 SG_ CellHeatMode_PermitStatus : 22|1@1+ (1,0) [0|1] ""  PC,MBMU

BO_ 2148749666 S2L_SUMDATA1__34: 8 SBMU
 SG_ CellHeatMode_Status : 4|1@1+ (1,0) [0|1] ""  PC,MBMU
 SG_ CellHeatMode_PermitStatus : 22|1@1+ (1,0) [0|1] ""  PC,MBMU

BO_ 2148749667 S2L_SUMDATA1__35: 8 SBMU
 SG_ CellHeatMode_Status : 4|1@1+ (1,0) [0|1] ""  PC,MBMU
 SG_ CellHeatMode_PermitStatus : 22|1@1+ (1,0) [0|1] ""  PC,MBMU

BO_ 2148749668 S2L_SUMDATA1__36: 8 SBMU
 SG_ CellHeatMode_Status : 4|1@1+ (1,0) [0|1] ""  PC,MBMU
 SG_ CellHeatMode_PermitStatus : 22|1@1+ (1,0) [0|1] ""  PC,MBMU

BO_ 2148749669 S2L_SUMDATA1__37: 8 SBMU
 SG_ CellHeatMode_Status : 4|1@1+ (1,0) [0|1] ""  PC,MBMU
 SG_ CellHeatMode_PermitStatus : 22|1@1+ (1,0) [0|1] ""  PC,MBMU

BO_ 2148749670 S2L_SUMDATA1__38: 8 SBMU
 SG_ CellHeatMode_Status : 4|1@1+ (1,0) [0|1] ""  PC,MBMU
 SG_ CellHeatMode_PermitStatus : 22|1@1+ (1,0) [0|1] ""  PC,MBMU

CM_ SG_ 2339635037 S2A_SUMDATA3_CUS_Reserve1_29 "客户预留数据";
CM_ SG_ 2339635037 S2A_SUMDATA3_CUS_Reserve2_29 "客户预留数据";
CM_ SG_ 2339635037 S2A_SUMDATA3_CUS_Reserve3_29 "客户预留数据";
CM_ SG_ 2339635037 S2A_SUMDATA3_CUS_Reserve4_29 "客户预留数据";
CM_ SG_ 2339635037 S2A_SUMDATA3_CUS_Reserve5_29 "客户预留数据";
CM_ SG_ 2339635037 S2A_SUMDATA3_CUS_Reserve6_29 "客户预留数据";
CM_ SG_ 2339635037 S2A_SUMDATA3_CUS_Reserve7_29 "客户预留数据";
CM_ SG_ 2339635037 S2A_SUMDATA3_CUS_Reserve8_29 "客户预留数据";
CM_ SG_ 2339635038 S2A_SUMDATA3_CUS_Reserve1_30 "客户预留数据";
CM_ SG_ 2339635038 S2A_SUMDATA3_CUS_Reserve2_30 "客户预留数据";
CM_ SG_ 2339635038 S2A_SUMDATA3_CUS_Reserve3_30 "客户预留数据";
CM_ SG_ 2339635038 S2A_SUMDATA3_CUS_Reserve4_30 "客户预留数据";
CM_ SG_ 2339635038 S2A_SUMDATA3_CUS_Reserve5_30 "客户预留数据";
CM_ SG_ 2339635038 S2A_SUMDATA3_CUS_Reserve6_30 "客户预留数据";
CM_ SG_ 2339635038 S2A_SUMDATA3_CUS_Reserve7_30 "客户预留数据";
CM_ SG_ 2339635038 S2A_SUMDATA3_CUS_Reserve8_30 "客户预留数据";
CM_ SG_ 2339635039 S2A_SUMDATA3_CUS_Reserve1_31 "客户预留数据";
CM_ SG_ 2339635039 S2A_SUMDATA3_CUS_Reserve2_31 "客户预留数据";
CM_ SG_ 2339635039 S2A_SUMDATA3_CUS_Reserve3_31 "客户预留数据";
CM_ SG_ 2339635039 S2A_SUMDATA3_CUS_Reserve4_31 "客户预留数据";
CM_ SG_ 2339635039 S2A_SUMDATA3_CUS_Reserve5_31 "客户预留数据";
CM_ SG_ 2339635039 S2A_SUMDATA3_CUS_Reserve6_31 "客户预留数据";
CM_ SG_ 2339635039 S2A_SUMDATA3_CUS_Reserve7_31 "客户预留数据";
CM_ SG_ 2339635039 S2A_SUMDATA3_CUS_Reserve8_31 "客户预留数据";
CM_ SG_ 2339635040 S2A_SUMDATA3_CUS_Reserve1_32 "客户预留数据";
CM_ SG_ 2339635040 S2A_SUMDATA3_CUS_Reserve2_32 "客户预留数据";
CM_ SG_ 2339635040 S2A_SUMDATA3_CUS_Reserve3_32 "客户预留数据";
CM_ SG_ 2339635040 S2A_SUMDATA3_CUS_Reserve4_32 "客户预留数据";
CM_ SG_ 2339635040 S2A_SUMDATA3_CUS_Reserve5_32 "客户预留数据";
CM_ SG_ 2339635040 S2A_SUMDATA3_CUS_Reserve6_32 "客户预留数据";
CM_ SG_ 2339635040 S2A_SUMDATA3_CUS_Reserve7_32 "客户预留数据";
CM_ SG_ 2339635040 S2A_SUMDATA3_CUS_Reserve8_32 "客户预留数据";
CM_ SG_ 2339635041 S2A_SUMDATA3_CUS_Reserve1_33 "客户预留数据";
CM_ SG_ 2339635041 S2A_SUMDATA3_CUS_Reserve2_33 "客户预留数据";
CM_ SG_ 2339635041 S2A_SUMDATA3_CUS_Reserve3_33 "客户预留数据";
CM_ SG_ 2339635041 S2A_SUMDATA3_CUS_Reserve4_33 "客户预留数据";
CM_ SG_ 2339635041 S2A_SUMDATA3_CUS_Reserve5_33 "客户预留数据";
CM_ SG_ 2339635041 S2A_SUMDATA3_CUS_Reserve6_33 "客户预留数据";
CM_ SG_ 2339635041 S2A_SUMDATA3_CUS_Reserve7_33 "客户预留数据";
CM_ SG_ 2339635041 S2A_SUMDATA3_CUS_Reserve8_33 "客户预留数据";
CM_ SG_ 2339635042 S2A_SUMDATA3_CUS_Reserve1_34 "客户预留数据";
CM_ SG_ 2339635042 S2A_SUMDATA3_CUS_Reserve2_34 "客户预留数据";
CM_ SG_ 2339635042 S2A_SUMDATA3_CUS_Reserve3_34 "客户预留数据";
CM_ SG_ 2339635042 S2A_SUMDATA3_CUS_Reserve4_34 "客户预留数据";
CM_ SG_ 2339635042 S2A_SUMDATA3_CUS_Reserve5_34 "客户预留数据";
CM_ SG_ 2339635042 S2A_SUMDATA3_CUS_Reserve6_34 "客户预留数据";
CM_ SG_ 2339635042 S2A_SUMDATA3_CUS_Reserve7_34 "客户预留数据";
CM_ SG_ 2339635042 S2A_SUMDATA3_CUS_Reserve8_34 "客户预留数据";
CM_ SG_ 2339635043 S2A_SUMDATA3_CUS_Reserve1_35 "客户预留数据";
CM_ SG_ 2339635043 S2A_SUMDATA3_CUS_Reserve2_35 "客户预留数据";
CM_ SG_ 2339635043 S2A_SUMDATA3_CUS_Reserve3_35 "客户预留数据";
CM_ SG_ 2339635043 S2A_SUMDATA3_CUS_Reserve4_35 "客户预留数据";
CM_ SG_ 2339635043 S2A_SUMDATA3_CUS_Reserve5_35 "客户预留数据";
CM_ SG_ 2339635043 S2A_SUMDATA3_CUS_Reserve6_35 "客户预留数据";
CM_ SG_ 2339635043 S2A_SUMDATA3_CUS_Reserve7_35 "客户预留数据";
CM_ SG_ 2339635043 S2A_SUMDATA3_CUS_Reserve8_35 "客户预留数据";
CM_ SG_ 2339635044 S2A_SUMDATA3_CUS_Reserve1_36 "客户预留数据";
CM_ SG_ 2339635044 S2A_SUMDATA3_CUS_Reserve2_36 "客户预留数据";
CM_ SG_ 2339635044 S2A_SUMDATA3_CUS_Reserve3_36 "客户预留数据";
CM_ SG_ 2339635044 S2A_SUMDATA3_CUS_Reserve4_36 "客户预留数据";
CM_ SG_ 2339635044 S2A_SUMDATA3_CUS_Reserve5_36 "客户预留数据";
CM_ SG_ 2339635044 S2A_SUMDATA3_CUS_Reserve6_36 "客户预留数据";
CM_ SG_ 2339635044 S2A_SUMDATA3_CUS_Reserve7_36 "客户预留数据";
CM_ SG_ 2339635044 S2A_SUMDATA3_CUS_Reserve8_36 "客户预留数据";
CM_ SG_ 2339635045 S2A_SUMDATA3_CUS_Reserve1_37 "客户预留数据";
CM_ SG_ 2339635045 S2A_SUMDATA3_CUS_Reserve2_37 "客户预留数据";
CM_ SG_ 2339635045 S2A_SUMDATA3_CUS_Reserve3_37 "客户预留数据";
CM_ SG_ 2339635045 S2A_SUMDATA3_CUS_Reserve4_37 "客户预留数据";
CM_ SG_ 2339635045 S2A_SUMDATA3_CUS_Reserve5_37 "客户预留数据";
CM_ SG_ 2339635045 S2A_SUMDATA3_CUS_Reserve6_37 "客户预留数据";
CM_ SG_ 2339635045 S2A_SUMDATA3_CUS_Reserve7_37 "客户预留数据";
CM_ SG_ 2339635045 S2A_SUMDATA3_CUS_Reserve8_37 "客户预留数据";
CM_ SG_ 2339635046 S2A_SUMDATA3_CUS_Reserve1_38 "客户预留数据";
CM_ SG_ 2339635046 S2A_SUMDATA3_CUS_Reserve2_38 "客户预留数据";
CM_ SG_ 2339635046 S2A_SUMDATA3_CUS_Reserve3_38 "客户预留数据";
CM_ SG_ 2339635046 S2A_SUMDATA3_CUS_Reserve4_38 "客户预留数据";
CM_ SG_ 2339635046 S2A_SUMDATA3_CUS_Reserve5_38 "客户预留数据";
CM_ SG_ 2339635046 S2A_SUMDATA3_CUS_Reserve6_38 "客户预留数据";
CM_ SG_ 2339635046 S2A_SUMDATA3_CUS_Reserve7_38 "客户预留数据";
CM_ SG_ 2339635046 S2A_SUMDATA3_CUS_Reserve8_38 "客户预留数据";
CM_ SG_ 2339635047 S2A_SUMDATA3_CUS_Reserve1_39 "客户预留数据";
CM_ SG_ 2339635047 S2A_SUMDATA3_CUS_Reserve2_39 "客户预留数据";
CM_ SG_ 2339635047 S2A_SUMDATA3_CUS_Reserve3_39 "客户预留数据";
CM_ SG_ 2339635047 S2A_SUMDATA3_CUS_Reserve4_39 "客户预留数据";
CM_ SG_ 2339635047 S2A_SUMDATA3_CUS_Reserve5_39 "客户预留数据";
CM_ SG_ 2339635047 S2A_SUMDATA3_CUS_Reserve6_39 "客户预留数据";
CM_ SG_ 2339635047 S2A_SUMDATA3_CUS_Reserve7_39 "客户预留数据";
CM_ SG_ 2339635047 S2A_SUMDATA3_CUS_Reserve8_39 "客户预留数据";
CM_ SG_ 2339635048 S2A_SUMDATA3_CUS_Reserve1_40 "客户预留数据";
CM_ SG_ 2339635048 S2A_SUMDATA3_CUS_Reserve2_40 "客户预留数据";
CM_ SG_ 2339635048 S2A_SUMDATA3_CUS_Reserve3_40 "客户预留数据";
CM_ SG_ 2339635048 S2A_SUMDATA3_CUS_Reserve4_40 "客户预留数据";
CM_ SG_ 2339635048 S2A_SUMDATA3_CUS_Reserve5_40 "客户预留数据";
CM_ SG_ 2339635048 S2A_SUMDATA3_CUS_Reserve6_40 "客户预留数据";
CM_ SG_ 2339635048 S2A_SUMDATA3_CUS_Reserve7_40 "客户预留数据";
CM_ SG_ 2339635048 S2A_SUMDATA3_CUS_Reserve8_40 "客户预留数据";
CM_ SG_ 2339635049 S2A_SUMDATA3_CUS_Reserve1_41 "客户预留数据";
CM_ SG_ 2339635049 S2A_SUMDATA3_CUS_Reserve2_41 "客户预留数据";
CM_ SG_ 2339635049 S2A_SUMDATA3_CUS_Reserve3_41 "客户预留数据";
CM_ SG_ 2339635049 S2A_SUMDATA3_CUS_Reserve4_41 "客户预留数据";
CM_ SG_ 2339635049 S2A_SUMDATA3_CUS_Reserve5_41 "客户预留数据";
CM_ SG_ 2339635049 S2A_SUMDATA3_CUS_Reserve6_41 "客户预留数据";
CM_ SG_ 2339635049 S2A_SUMDATA3_CUS_Reserve7_41 "客户预留数据";
CM_ SG_ 2339635049 S2A_SUMDATA3_CUS_Reserve8_41 "客户预留数据";
CM_ SG_ 2339635050 S2A_SUMDATA3_CUS_Reserve1_42 "客户预留数据";
CM_ SG_ 2339635050 S2A_SUMDATA3_CUS_Reserve2_42 "客户预留数据";
CM_ SG_ 2339635050 S2A_SUMDATA3_CUS_Reserve3_42 "客户预留数据";
CM_ SG_ 2339635050 S2A_SUMDATA3_CUS_Reserve4_42 "客户预留数据";
CM_ SG_ 2339635050 S2A_SUMDATA3_CUS_Reserve5_42 "客户预留数据";
CM_ SG_ 2339635050 S2A_SUMDATA3_CUS_Reserve6_42 "客户预留数据";
CM_ SG_ 2339635050 S2A_SUMDATA3_CUS_Reserve7_42 "客户预留数据";
CM_ SG_ 2339635050 S2A_SUMDATA3_CUS_Reserve8_42 "客户预留数据";
CM_ SG_ 2339635051 S2A_SUMDATA3_CUS_Reserve1_43 "客户预留数据";
CM_ SG_ 2339635051 S2A_SUMDATA3_CUS_Reserve2_43 "客户预留数据";
CM_ SG_ 2339635051 S2A_SUMDATA3_CUS_Reserve3_43 "客户预留数据";
CM_ SG_ 2339635051 S2A_SUMDATA3_CUS_Reserve4_43 "客户预留数据";
CM_ SG_ 2339635051 S2A_SUMDATA3_CUS_Reserve5_43 "客户预留数据";
CM_ SG_ 2339635051 S2A_SUMDATA3_CUS_Reserve6_43 "客户预留数据";
CM_ SG_ 2339635051 S2A_SUMDATA3_CUS_Reserve7_43 "客户预留数据";
CM_ SG_ 2339635051 S2A_SUMDATA3_CUS_Reserve8_43 "客户预留数据";
CM_ SG_ 2339635052 S2A_SUMDATA3_CUS_Reserve1_44 "客户预留数据";
CM_ SG_ 2339635052 S2A_SUMDATA3_CUS_Reserve2_44 "客户预留数据";
CM_ SG_ 2339635052 S2A_SUMDATA3_CUS_Reserve3_44 "客户预留数据";
CM_ SG_ 2339635052 S2A_SUMDATA3_CUS_Reserve4_44 "客户预留数据";
CM_ SG_ 2339635052 S2A_SUMDATA3_CUS_Reserve5_44 "客户预留数据";
CM_ SG_ 2339635052 S2A_SUMDATA3_CUS_Reserve6_44 "客户预留数据";
CM_ SG_ 2339635052 S2A_SUMDATA3_CUS_Reserve7_44 "客户预留数据";
CM_ SG_ 2339635052 S2A_SUMDATA3_CUS_Reserve8_44 "客户预留数据";
CM_ SG_ 2339635053 S2A_SUMDATA3_CUS_Reserve1_45 "客户预留数据";
CM_ SG_ 2339635053 S2A_SUMDATA3_CUS_Reserve2_45 "客户预留数据";
CM_ SG_ 2339635053 S2A_SUMDATA3_CUS_Reserve3_45 "客户预留数据";
CM_ SG_ 2339635053 S2A_SUMDATA3_CUS_Reserve4_45 "客户预留数据";
CM_ SG_ 2339635053 S2A_SUMDATA3_CUS_Reserve5_45 "客户预留数据";
CM_ SG_ 2339635053 S2A_SUMDATA3_CUS_Reserve6_45 "客户预留数据";
CM_ SG_ 2339635053 S2A_SUMDATA3_CUS_Reserve7_45 "客户预留数据";
CM_ SG_ 2339635053 S2A_SUMDATA3_CUS_Reserve8_45 "客户预留数据";
CM_ SG_ 2339635054 S2A_SUMDATA3_CUS_Reserve1_46 "客户预留数据";
CM_ SG_ 2339635054 S2A_SUMDATA3_CUS_Reserve2_46 "客户预留数据";
CM_ SG_ 2339635054 S2A_SUMDATA3_CUS_Reserve3_46 "客户预留数据";
CM_ SG_ 2339635054 S2A_SUMDATA3_CUS_Reserve4_46 "客户预留数据";
CM_ SG_ 2339635054 S2A_SUMDATA3_CUS_Reserve5_46 "客户预留数据";
CM_ SG_ 2339635054 S2A_SUMDATA3_CUS_Reserve6_46 "客户预留数据";
CM_ SG_ 2339635054 S2A_SUMDATA3_CUS_Reserve7_46 "客户预留数据";
CM_ SG_ 2339635054 S2A_SUMDATA3_CUS_Reserve8_46 "客户预留数据";
CM_ SG_ 2339635055 S2A_SUMDATA3_CUS_Reserve1_47 "客户预留数据";
CM_ SG_ 2339635055 S2A_SUMDATA3_CUS_Reserve2_47 "客户预留数据";
CM_ SG_ 2339635055 S2A_SUMDATA3_CUS_Reserve3_47 "客户预留数据";
CM_ SG_ 2339635055 S2A_SUMDATA3_CUS_Reserve4_47 "客户预留数据";
CM_ SG_ 2339635055 S2A_SUMDATA3_CUS_Reserve5_47 "客户预留数据";
CM_ SG_ 2339635055 S2A_SUMDATA3_CUS_Reserve6_47 "客户预留数据";
CM_ SG_ 2339635055 S2A_SUMDATA3_CUS_Reserve7_47 "客户预留数据";
CM_ SG_ 2339635055 S2A_SUMDATA3_CUS_Reserve8_47 "客户预留数据";
CM_ SG_ 2339635056 S2A_SUMDATA3_CUS_Reserve1_48 "客户预留数据";
CM_ SG_ 2339635056 S2A_SUMDATA3_CUS_Reserve2_48 "客户预留数据";
CM_ SG_ 2339635056 S2A_SUMDATA3_CUS_Reserve3_48 "客户预留数据";
CM_ SG_ 2339635056 S2A_SUMDATA3_CUS_Reserve4_48 "客户预留数据";
CM_ SG_ 2339635056 S2A_SUMDATA3_CUS_Reserve5_48 "客户预留数据";
CM_ SG_ 2339635056 S2A_SUMDATA3_CUS_Reserve6_48 "客户预留数据";
CM_ SG_ 2339635056 S2A_SUMDATA3_CUS_Reserve7_48 "客户预留数据";
CM_ SG_ 2339635056 S2A_SUMDATA3_CUS_Reserve8_48 "客户预留数据";
CM_ SG_ 2339635057 S2A_SUMDATA3_CUS_Reserve1_49 "客户预留数据";
CM_ SG_ 2339635057 S2A_SUMDATA3_CUS_Reserve2_49 "客户预留数据";
CM_ SG_ 2339635057 S2A_SUMDATA3_CUS_Reserve3_49 "客户预留数据";
CM_ SG_ 2339635057 S2A_SUMDATA3_CUS_Reserve4_49 "客户预留数据";
CM_ SG_ 2339635057 S2A_SUMDATA3_CUS_Reserve5_49 "客户预留数据";
CM_ SG_ 2339635057 S2A_SUMDATA3_CUS_Reserve6_49 "客户预留数据";
CM_ SG_ 2339635057 S2A_SUMDATA3_CUS_Reserve7_49 "客户预留数据";
CM_ SG_ 2339635057 S2A_SUMDATA3_CUS_Reserve8_49 "客户预留数据";
CM_ SG_ 2339635058 S2A_SUMDATA3_CUS_Reserve1_50 "客户预留数据";
CM_ SG_ 2339635058 S2A_SUMDATA3_CUS_Reserve2_50 "客户预留数据";
CM_ SG_ 2339635058 S2A_SUMDATA3_CUS_Reserve3_50 "客户预留数据";
CM_ SG_ 2339635058 S2A_SUMDATA3_CUS_Reserve4_50 "客户预留数据";
CM_ SG_ 2339635058 S2A_SUMDATA3_CUS_Reserve5_50 "客户预留数据";
CM_ SG_ 2339635058 S2A_SUMDATA3_CUS_Reserve6_50 "客户预留数据";
CM_ SG_ 2339635058 S2A_SUMDATA3_CUS_Reserve7_50 "客户预留数据";
CM_ SG_ 2339635058 S2A_SUMDATA3_CUS_Reserve8_50 "客户预留数据";
CM_ SG_ 2339635059 S2A_SUMDATA3_CUS_Reserve1_51 "客户预留数据";
CM_ SG_ 2339635059 S2A_SUMDATA3_CUS_Reserve2_51 "客户预留数据";
CM_ SG_ 2339635059 S2A_SUMDATA3_CUS_Reserve3_51 "客户预留数据";
CM_ SG_ 2339635059 S2A_SUMDATA3_CUS_Reserve4_51 "客户预留数据";
CM_ SG_ 2339635059 S2A_SUMDATA3_CUS_Reserve5_51 "客户预留数据";
CM_ SG_ 2339635059 S2A_SUMDATA3_CUS_Reserve6_51 "客户预留数据";
CM_ SG_ 2339635059 S2A_SUMDATA3_CUS_Reserve7_51 "客户预留数据";
CM_ SG_ 2339635059 S2A_SUMDATA3_CUS_Reserve8_51 "客户预留数据";
CM_ SG_ 2339635060 S2A_SUMDATA3_CUS_Reserve1_52 "客户预留数据";
CM_ SG_ 2339635060 S2A_SUMDATA3_CUS_Reserve2_52 "客户预留数据";
CM_ SG_ 2339635060 S2A_SUMDATA3_CUS_Reserve3_52 "客户预留数据";
CM_ SG_ 2339635060 S2A_SUMDATA3_CUS_Reserve4_52 "客户预留数据";
CM_ SG_ 2339635060 S2A_SUMDATA3_CUS_Reserve5_52 "客户预留数据";
CM_ SG_ 2339635060 S2A_SUMDATA3_CUS_Reserve6_52 "客户预留数据";
CM_ SG_ 2339635060 S2A_SUMDATA3_CUS_Reserve7_52 "客户预留数据";
CM_ SG_ 2339635060 S2A_SUMDATA3_CUS_Reserve8_52 "客户预留数据";
CM_ SG_ 2339635061 S2A_SUMDATA3_CUS_Reserve1_53 "客户预留数据";
CM_ SG_ 2339635061 S2A_SUMDATA3_CUS_Reserve2_53 "客户预留数据";
CM_ SG_ 2339635061 S2A_SUMDATA3_CUS_Reserve3_53 "客户预留数据";
CM_ SG_ 2339635061 S2A_SUMDATA3_CUS_Reserve4_53 "客户预留数据";
CM_ SG_ 2339635061 S2A_SUMDATA3_CUS_Reserve5_53 "客户预留数据";
CM_ SG_ 2339635061 S2A_SUMDATA3_CUS_Reserve6_53 "客户预留数据";
CM_ SG_ 2339635061 S2A_SUMDATA3_CUS_Reserve7_53 "客户预留数据";
CM_ SG_ 2339635061 S2A_SUMDATA3_CUS_Reserve8_53 "客户预留数据";
CM_ SG_ 2339635062 S2A_SUMDATA3_CUS_Reserve1_54 "客户预留数据";
CM_ SG_ 2339635062 S2A_SUMDATA3_CUS_Reserve2_54 "客户预留数据";
CM_ SG_ 2339635062 S2A_SUMDATA3_CUS_Reserve3_54 "客户预留数据";
CM_ SG_ 2339635062 S2A_SUMDATA3_CUS_Reserve4_54 "客户预留数据";
CM_ SG_ 2339635062 S2A_SUMDATA3_CUS_Reserve5_54 "客户预留数据";
CM_ SG_ 2339635062 S2A_SUMDATA3_CUS_Reserve6_54 "客户预留数据";
CM_ SG_ 2339635062 S2A_SUMDATA3_CUS_Reserve7_54 "客户预留数据";
CM_ SG_ 2339635062 S2A_SUMDATA3_CUS_Reserve8_54 "客户预留数据";
CM_ SG_ 2339635063 S2A_SUMDATA3_CUS_Reserve1_55 "客户预留数据";
CM_ SG_ 2339635063 S2A_SUMDATA3_CUS_Reserve2_55 "客户预留数据";
CM_ SG_ 2339635063 S2A_SUMDATA3_CUS_Reserve3_55 "客户预留数据";
CM_ SG_ 2339635063 S2A_SUMDATA3_CUS_Reserve4_55 "客户预留数据";
CM_ SG_ 2339635063 S2A_SUMDATA3_CUS_Reserve5_55 "客户预留数据";
CM_ SG_ 2339635063 S2A_SUMDATA3_CUS_Reserve6_55 "客户预留数据";
CM_ SG_ 2339635063 S2A_SUMDATA3_CUS_Reserve7_55 "客户预留数据";
CM_ SG_ 2339635063 S2A_SUMDATA3_CUS_Reserve8_55 "客户预留数据";
CM_ SG_ 2339635064 S2A_SUMDATA3_CUS_Reserve1_56 "客户预留数据";
CM_ SG_ 2339635064 S2A_SUMDATA3_CUS_Reserve2_56 "客户预留数据";
CM_ SG_ 2339635064 S2A_SUMDATA3_CUS_Reserve3_56 "客户预留数据";
CM_ SG_ 2339635064 S2A_SUMDATA3_CUS_Reserve4_56 "客户预留数据";
CM_ SG_ 2339635064 S2A_SUMDATA3_CUS_Reserve5_56 "客户预留数据";
CM_ SG_ 2339635064 S2A_SUMDATA3_CUS_Reserve6_56 "客户预留数据";
CM_ SG_ 2339635064 S2A_SUMDATA3_CUS_Reserve7_56 "客户预留数据";
CM_ SG_ 2339635064 S2A_SUMDATA3_CUS_Reserve8_56 "客户预留数据";
CM_ SG_ 2339635065 S2A_SUMDATA3_CUS_Reserve1_57 "客户预留数据";
CM_ SG_ 2339635065 S2A_SUMDATA3_CUS_Reserve2_57 "客户预留数据";
CM_ SG_ 2339635065 S2A_SUMDATA3_CUS_Reserve3_57 "客户预留数据";
CM_ SG_ 2339635065 S2A_SUMDATA3_CUS_Reserve4_57 "客户预留数据";
CM_ SG_ 2339635065 S2A_SUMDATA3_CUS_Reserve5_57 "客户预留数据";
CM_ SG_ 2339635065 S2A_SUMDATA3_CUS_Reserve6_57 "客户预留数据";
CM_ SG_ 2339635065 S2A_SUMDATA3_CUS_Reserve7_57 "客户预留数据";
CM_ SG_ 2339635065 S2A_SUMDATA3_CUS_Reserve8_57 "客户预留数据";
CM_ SG_ 2339635066 S2A_SUMDATA3_CUS_Reserve1_58 "客户预留数据";
CM_ SG_ 2339635066 S2A_SUMDATA3_CUS_Reserve2_58 "客户预留数据";
CM_ SG_ 2339635066 S2A_SUMDATA3_CUS_Reserve3_58 "客户预留数据";
CM_ SG_ 2339635066 S2A_SUMDATA3_CUS_Reserve4_58 "客户预留数据";
CM_ SG_ 2339635066 S2A_SUMDATA3_CUS_Reserve5_58 "客户预留数据";
CM_ SG_ 2339635066 S2A_SUMDATA3_CUS_Reserve6_58 "客户预留数据";
CM_ SG_ 2339635066 S2A_SUMDATA3_CUS_Reserve7_58 "客户预留数据";
CM_ SG_ 2339635066 S2A_SUMDATA3_CUS_Reserve8_58 "客户预留数据";
CM_ SG_ 2339635067 S2A_SUMDATA3_CUS_Reserve1_59 "客户预留数据";
CM_ SG_ 2339635067 S2A_SUMDATA3_CUS_Reserve2_59 "客户预留数据";
CM_ SG_ 2339635067 S2A_SUMDATA3_CUS_Reserve3_59 "客户预留数据";
CM_ SG_ 2339635067 S2A_SUMDATA3_CUS_Reserve4_59 "客户预留数据";
CM_ SG_ 2339635067 S2A_SUMDATA3_CUS_Reserve5_59 "客户预留数据";
CM_ SG_ 2339635067 S2A_SUMDATA3_CUS_Reserve6_59 "客户预留数据";
CM_ SG_ 2339635067 S2A_SUMDATA3_CUS_Reserve7_59 "客户预留数据";
CM_ SG_ 2339635067 S2A_SUMDATA3_CUS_Reserve8_59 "客户预留数据";
CM_ SG_ 2339635068 S2A_SUMDATA3_CUS_Reserve1_60 "客户预留数据";
CM_ SG_ 2339635068 S2A_SUMDATA3_CUS_Reserve2_60 "客户预留数据";
CM_ SG_ 2339635068 S2A_SUMDATA3_CUS_Reserve3_60 "客户预留数据";
CM_ SG_ 2339635068 S2A_SUMDATA3_CUS_Reserve4_60 "客户预留数据";
CM_ SG_ 2339635068 S2A_SUMDATA3_CUS_Reserve5_60 "客户预留数据";
CM_ SG_ 2339635068 S2A_SUMDATA3_CUS_Reserve6_60 "客户预留数据";
CM_ SG_ 2339635068 S2A_SUMDATA3_CUS_Reserve7_60 "客户预留数据";
CM_ SG_ 2339635068 S2A_SUMDATA3_CUS_Reserve8_60 "客户预留数据";
CM_ SG_ 2339635069 S2A_SUMDATA3_CUS_Reserve1_61 "客户预留数据";
CM_ SG_ 2339635069 S2A_SUMDATA3_CUS_Reserve2_61 "客户预留数据";
CM_ SG_ 2339635069 S2A_SUMDATA3_CUS_Reserve3_61 "客户预留数据";
CM_ SG_ 2339635069 S2A_SUMDATA3_CUS_Reserve4_61 "客户预留数据";
CM_ SG_ 2339635069 S2A_SUMDATA3_CUS_Reserve5_61 "客户预留数据";
CM_ SG_ 2339635069 S2A_SUMDATA3_CUS_Reserve6_61 "客户预留数据";
CM_ SG_ 2339635069 S2A_SUMDATA3_CUS_Reserve7_61 "客户预留数据";
CM_ SG_ 2339635069 S2A_SUMDATA3_CUS_Reserve8_61 "客户预留数据";
CM_ SG_ 2339635070 S2A_SUMDATA3_CUS_Reserve1_62 "客户预留数据";
CM_ SG_ 2339635070 S2A_SUMDATA3_CUS_Reserve2_62 "客户预留数据";
CM_ SG_ 2339635070 S2A_SUMDATA3_CUS_Reserve3_62 "客户预留数据";
CM_ SG_ 2339635070 S2A_SUMDATA3_CUS_Reserve4_62 "客户预留数据";
CM_ SG_ 2339635070 S2A_SUMDATA3_CUS_Reserve5_62 "客户预留数据";
CM_ SG_ 2339635070 S2A_SUMDATA3_CUS_Reserve6_62 "客户预留数据";
CM_ SG_ 2339635070 S2A_SUMDATA3_CUS_Reserve7_62 "客户预留数据";
CM_ SG_ 2339635070 S2A_SUMDATA3_CUS_Reserve8_62 "客户预留数据";
CM_ SG_ 2339635071 S2A_SUMDATA3_CUS_Reserve1_63 "客户预留数据";
CM_ SG_ 2339635071 S2A_SUMDATA3_CUS_Reserve2_63 "客户预留数据";
CM_ SG_ 2339635071 S2A_SUMDATA3_CUS_Reserve3_63 "客户预留数据";
CM_ SG_ 2339635071 S2A_SUMDATA3_CUS_Reserve4_63 "客户预留数据";
CM_ SG_ 2339635071 S2A_SUMDATA3_CUS_Reserve5_63 "客户预留数据";
CM_ SG_ 2339635071 S2A_SUMDATA3_CUS_Reserve6_63 "客户预留数据";
CM_ SG_ 2339635071 S2A_SUMDATA3_CUS_Reserve7_63 "客户预留数据";
CM_ SG_ 2339635071 S2A_SUMDATA3_CUS_Reserve8_63 "客户预留数据";
CM_ SG_ 2339700545 S2A_SUMDATA4_CUS_Reserve1_01 "客户预留数据";
CM_ SG_ 2339700545 S2A_SUMDATA4_CUS_Reserve2_01 "客户预留数据";
CM_ SG_ 2339700545 S2A_SUMDATA4_CUS_Reserve3_01 "客户预留数据";
CM_ SG_ 2339700545 S2A_SUMDATA4_CUS_Reserve4_01 "客户预留数据";
CM_ SG_ 2339700545 S2A_SUMDATA4_CUS_Reserve5_01 "客户预留数据";
CM_ SG_ 2339700545 S2A_SUMDATA4_CUS_Reserve6_01 "客户预留数据";
CM_ SG_ 2339700545 S2A_SUMDATA4_CUS_Reserve7_01 "客户预留数据";
CM_ SG_ 2339700545 S2A_SUMDATA4_CUS_Reserve8_01 "客户预留数据";
CM_ SG_ 2339700546 S2A_SUMDATA4_CUS_Reserve1_02 "客户预留数据";
CM_ SG_ 2339700546 S2A_SUMDATA4_CUS_Reserve2_02 "客户预留数据";
CM_ SG_ 2339700546 S2A_SUMDATA4_CUS_Reserve3_02 "客户预留数据";
CM_ SG_ 2339700546 S2A_SUMDATA4_CUS_Reserve4_02 "客户预留数据";
CM_ SG_ 2339700546 S2A_SUMDATA4_CUS_Reserve5_02 "客户预留数据";
CM_ SG_ 2339700546 S2A_SUMDATA4_CUS_Reserve6_02 "客户预留数据";
CM_ SG_ 2339700546 S2A_SUMDATA4_CUS_Reserve7_02 "客户预留数据";
CM_ SG_ 2339700546 S2A_SUMDATA4_CUS_Reserve8_02 "客户预留数据";
CM_ SG_ 2339700547 S2A_SUMDATA4_CUS_Reserve1_03 "客户预留数据";
CM_ SG_ 2339700547 S2A_SUMDATA4_CUS_Reserve2_03 "客户预留数据";
CM_ SG_ 2339700547 S2A_SUMDATA4_CUS_Reserve3_03 "客户预留数据";
CM_ SG_ 2339700547 S2A_SUMDATA4_CUS_Reserve4_03 "客户预留数据";
CM_ SG_ 2339700547 S2A_SUMDATA4_CUS_Reserve5_03 "客户预留数据";
CM_ SG_ 2339700547 S2A_SUMDATA4_CUS_Reserve6_03 "客户预留数据";
CM_ SG_ 2339700547 S2A_SUMDATA4_CUS_Reserve7_03 "客户预留数据";
CM_ SG_ 2339700547 S2A_SUMDATA4_CUS_Reserve8_03 "客户预留数据";
CM_ SG_ 2339700548 S2A_SUMDATA4_CUS_Reserve1_04 "客户预留数据";
CM_ SG_ 2339700548 S2A_SUMDATA4_CUS_Reserve2_04 "客户预留数据";
CM_ SG_ 2339700548 S2A_SUMDATA4_CUS_Reserve3_04 "客户预留数据";
CM_ SG_ 2339700548 S2A_SUMDATA4_CUS_Reserve4_04 "客户预留数据";
CM_ SG_ 2339700548 S2A_SUMDATA4_CUS_Reserve5_04 "客户预留数据";
CM_ SG_ 2339700548 S2A_SUMDATA4_CUS_Reserve6_04 "客户预留数据";
CM_ SG_ 2339700548 S2A_SUMDATA4_CUS_Reserve7_04 "客户预留数据";
CM_ SG_ 2339700548 S2A_SUMDATA4_CUS_Reserve8_04 "客户预留数据";
CM_ SG_ 2339700549 S2A_SUMDATA4_CUS_Reserve1_05 "客户预留数据";
CM_ SG_ 2339700549 S2A_SUMDATA4_CUS_Reserve2_05 "客户预留数据";
CM_ SG_ 2339700549 S2A_SUMDATA4_CUS_Reserve3_05 "客户预留数据";
CM_ SG_ 2339700549 S2A_SUMDATA4_CUS_Reserve4_05 "客户预留数据";
CM_ SG_ 2339700549 S2A_SUMDATA4_CUS_Reserve5_05 "客户预留数据";
CM_ SG_ 2339700549 S2A_SUMDATA4_CUS_Reserve6_05 "客户预留数据";
CM_ SG_ 2339700549 S2A_SUMDATA4_CUS_Reserve7_05 "客户预留数据";
CM_ SG_ 2339700549 S2A_SUMDATA4_CUS_Reserve8_05 "客户预留数据";
CM_ SG_ 2339700550 S2A_SUMDATA4_CUS_Reserve1_06 "客户预留数据";
CM_ SG_ 2339700550 S2A_SUMDATA4_CUS_Reserve2_06 "客户预留数据";
CM_ SG_ 2339700550 S2A_SUMDATA4_CUS_Reserve3_06 "客户预留数据";
CM_ SG_ 2339700550 S2A_SUMDATA4_CUS_Reserve4_06 "客户预留数据";
CM_ SG_ 2339700550 S2A_SUMDATA4_CUS_Reserve5_06 "客户预留数据";
CM_ SG_ 2339700550 S2A_SUMDATA4_CUS_Reserve6_06 "客户预留数据";
CM_ SG_ 2339700550 S2A_SUMDATA4_CUS_Reserve7_06 "客户预留数据";
CM_ SG_ 2339700550 S2A_SUMDATA4_CUS_Reserve8_06 "客户预留数据";
CM_ SG_ 2339700551 S2A_SUMDATA4_CUS_Reserve1_07 "客户预留数据";
CM_ SG_ 2339700551 S2A_SUMDATA4_CUS_Reserve2_07 "客户预留数据";
CM_ SG_ 2339700551 S2A_SUMDATA4_CUS_Reserve3_07 "客户预留数据";
CM_ SG_ 2339700551 S2A_SUMDATA4_CUS_Reserve4_07 "客户预留数据";
CM_ SG_ 2339700551 S2A_SUMDATA4_CUS_Reserve5_07 "客户预留数据";
CM_ SG_ 2339700551 S2A_SUMDATA4_CUS_Reserve6_07 "客户预留数据";
CM_ SG_ 2339700551 S2A_SUMDATA4_CUS_Reserve7_07 "客户预留数据";
CM_ SG_ 2339700551 S2A_SUMDATA4_CUS_Reserve8_07 "客户预留数据";
CM_ SG_ 2339700552 S2A_SUMDATA4_CUS_Reserve1_08 "客户预留数据";
CM_ SG_ 2339700552 S2A_SUMDATA4_CUS_Reserve2_08 "客户预留数据";
CM_ SG_ 2339700552 S2A_SUMDATA4_CUS_Reserve3_08 "客户预留数据";
CM_ SG_ 2339700552 S2A_SUMDATA4_CUS_Reserve4_08 "客户预留数据";
CM_ SG_ 2339700552 S2A_SUMDATA4_CUS_Reserve5_08 "客户预留数据";
CM_ SG_ 2339700552 S2A_SUMDATA4_CUS_Reserve6_08 "客户预留数据";
CM_ SG_ 2339700552 S2A_SUMDATA4_CUS_Reserve7_08 "客户预留数据";
CM_ SG_ 2339700552 S2A_SUMDATA4_CUS_Reserve8_08 "客户预留数据";
CM_ SG_ 2339700553 S2A_SUMDATA4_CUS_Reserve1_09 "客户预留数据";
CM_ SG_ 2339700553 S2A_SUMDATA4_CUS_Reserve2_09 "客户预留数据";
CM_ SG_ 2339700553 S2A_SUMDATA4_CUS_Reserve3_09 "客户预留数据";
CM_ SG_ 2339700553 S2A_SUMDATA4_CUS_Reserve4_09 "客户预留数据";
CM_ SG_ 2339700553 S2A_SUMDATA4_CUS_Reserve5_09 "客户预留数据";
CM_ SG_ 2339700553 S2A_SUMDATA4_CUS_Reserve6_09 "客户预留数据";
CM_ SG_ 2339700553 S2A_SUMDATA4_CUS_Reserve7_09 "客户预留数据";
CM_ SG_ 2339700553 S2A_SUMDATA4_CUS_Reserve8_09 "客户预留数据";
CM_ SG_ 2339700554 S2A_SUMDATA4_CUS_Reserve1_10 "客户预留数据";
CM_ SG_ 2339700554 S2A_SUMDATA4_CUS_Reserve2_10 "客户预留数据";
CM_ SG_ 2339700554 S2A_SUMDATA4_CUS_Reserve3_10 "客户预留数据";
CM_ SG_ 2339700554 S2A_SUMDATA4_CUS_Reserve4_10 "客户预留数据";
CM_ SG_ 2339700554 S2A_SUMDATA4_CUS_Reserve5_10 "客户预留数据";
CM_ SG_ 2339700554 S2A_SUMDATA4_CUS_Reserve6_10 "客户预留数据";
CM_ SG_ 2339700554 S2A_SUMDATA4_CUS_Reserve7_10 "客户预留数据";
CM_ SG_ 2339700554 S2A_SUMDATA4_CUS_Reserve8_10 "客户预留数据";
CM_ SG_ 2339700555 S2A_SUMDATA4_CUS_Reserve1_11 "客户预留数据";
CM_ SG_ 2339700555 S2A_SUMDATA4_CUS_Reserve2_11 "客户预留数据";
CM_ SG_ 2339700555 S2A_SUMDATA4_CUS_Reserve3_11 "客户预留数据";
CM_ SG_ 2339700555 S2A_SUMDATA4_CUS_Reserve4_11 "客户预留数据";
CM_ SG_ 2339700555 S2A_SUMDATA4_CUS_Reserve5_11 "客户预留数据";
CM_ SG_ 2339700555 S2A_SUMDATA4_CUS_Reserve6_11 "客户预留数据";
CM_ SG_ 2339700555 S2A_SUMDATA4_CUS_Reserve7_11 "客户预留数据";
CM_ SG_ 2339700555 S2A_SUMDATA4_CUS_Reserve8_11 "客户预留数据";
CM_ SG_ 2339700556 S2A_SUMDATA4_CUS_Reserve1_12 "客户预留数据";
CM_ SG_ 2339700556 S2A_SUMDATA4_CUS_Reserve2_12 "客户预留数据";
CM_ SG_ 2339700556 S2A_SUMDATA4_CUS_Reserve3_12 "客户预留数据";
CM_ SG_ 2339700556 S2A_SUMDATA4_CUS_Reserve4_12 "客户预留数据";
CM_ SG_ 2339700556 S2A_SUMDATA4_CUS_Reserve5_12 "客户预留数据";
CM_ SG_ 2339700556 S2A_SUMDATA4_CUS_Reserve6_12 "客户预留数据";
CM_ SG_ 2339700556 S2A_SUMDATA4_CUS_Reserve7_12 "客户预留数据";
CM_ SG_ 2339700556 S2A_SUMDATA4_CUS_Reserve8_12 "客户预留数据";
CM_ SG_ 2339700557 S2A_SUMDATA4_CUS_Reserve1_13 "客户预留数据";
CM_ SG_ 2339700557 S2A_SUMDATA4_CUS_Reserve2_13 "客户预留数据";
CM_ SG_ 2339700557 S2A_SUMDATA4_CUS_Reserve3_13 "客户预留数据";
CM_ SG_ 2339700557 S2A_SUMDATA4_CUS_Reserve4_13 "客户预留数据";
CM_ SG_ 2339700557 S2A_SUMDATA4_CUS_Reserve5_13 "客户预留数据";
CM_ SG_ 2339700557 S2A_SUMDATA4_CUS_Reserve6_13 "客户预留数据";
CM_ SG_ 2339700557 S2A_SUMDATA4_CUS_Reserve7_13 "客户预留数据";
CM_ SG_ 2339700557 S2A_SUMDATA4_CUS_Reserve8_13 "客户预留数据";
CM_ SG_ 2339700558 S2A_SUMDATA4_CUS_Reserve1_14 "客户预留数据";
CM_ SG_ 2339700558 S2A_SUMDATA4_CUS_Reserve2_14 "客户预留数据";
CM_ SG_ 2339700558 S2A_SUMDATA4_CUS_Reserve3_14 "客户预留数据";
CM_ SG_ 2339700558 S2A_SUMDATA4_CUS_Reserve4_14 "客户预留数据";
CM_ SG_ 2339700558 S2A_SUMDATA4_CUS_Reserve5_14 "客户预留数据";
CM_ SG_ 2339700558 S2A_SUMDATA4_CUS_Reserve6_14 "客户预留数据";
CM_ SG_ 2339700558 S2A_SUMDATA4_CUS_Reserve7_14 "客户预留数据";
CM_ SG_ 2339700558 S2A_SUMDATA4_CUS_Reserve8_14 "客户预留数据";
CM_ SG_ 2339700559 S2A_SUMDATA4_CUS_Reserve1_15 "客户预留数据";
CM_ SG_ 2339700559 S2A_SUMDATA4_CUS_Reserve2_15 "客户预留数据";
CM_ SG_ 2339700559 S2A_SUMDATA4_CUS_Reserve3_15 "客户预留数据";
CM_ SG_ 2339700559 S2A_SUMDATA4_CUS_Reserve4_15 "客户预留数据";
CM_ SG_ 2339700559 S2A_SUMDATA4_CUS_Reserve5_15 "客户预留数据";
CM_ SG_ 2339700559 S2A_SUMDATA4_CUS_Reserve6_15 "客户预留数据";
CM_ SG_ 2339700559 S2A_SUMDATA4_CUS_Reserve7_15 "客户预留数据";
CM_ SG_ 2339700559 S2A_SUMDATA4_CUS_Reserve8_15 "客户预留数据";
CM_ SG_ 2339700560 S2A_SUMDATA4_CUS_Reserve1_16 "客户预留数据";
CM_ SG_ 2339700560 S2A_SUMDATA4_CUS_Reserve2_16 "客户预留数据";
CM_ SG_ 2339700560 S2A_SUMDATA4_CUS_Reserve3_16 "客户预留数据";
CM_ SG_ 2339700560 S2A_SUMDATA4_CUS_Reserve4_16 "客户预留数据";
CM_ SG_ 2339700560 S2A_SUMDATA4_CUS_Reserve5_16 "客户预留数据";
CM_ SG_ 2339700560 S2A_SUMDATA4_CUS_Reserve6_16 "客户预留数据";
CM_ SG_ 2339700560 S2A_SUMDATA4_CUS_Reserve7_16 "客户预留数据";
CM_ SG_ 2339700560 S2A_SUMDATA4_CUS_Reserve8_16 "客户预留数据";
CM_ SG_ 2339700561 S2A_SUMDATA4_CUS_Reserve1_17 "客户预留数据";
CM_ SG_ 2339700561 S2A_SUMDATA4_CUS_Reserve2_17 "客户预留数据";
CM_ SG_ 2339700561 S2A_SUMDATA4_CUS_Reserve3_17 "客户预留数据";
CM_ SG_ 2339700561 S2A_SUMDATA4_CUS_Reserve4_17 "客户预留数据";
CM_ SG_ 2339700561 S2A_SUMDATA4_CUS_Reserve5_17 "客户预留数据";
CM_ SG_ 2339700561 S2A_SUMDATA4_CUS_Reserve6_17 "客户预留数据";
CM_ SG_ 2339700561 S2A_SUMDATA4_CUS_Reserve7_17 "客户预留数据";
CM_ SG_ 2339700561 S2A_SUMDATA4_CUS_Reserve8_17 "客户预留数据";
CM_ SG_ 2339700562 S2A_SUMDATA4_CUS_Reserve1_18 "客户预留数据";
CM_ SG_ 2339700562 S2A_SUMDATA4_CUS_Reserve2_18 "客户预留数据";
CM_ SG_ 2339700562 S2A_SUMDATA4_CUS_Reserve3_18 "客户预留数据";
CM_ SG_ 2339700562 S2A_SUMDATA4_CUS_Reserve4_18 "客户预留数据";
CM_ SG_ 2339700562 S2A_SUMDATA4_CUS_Reserve5_18 "客户预留数据";
CM_ SG_ 2339700562 S2A_SUMDATA4_CUS_Reserve6_18 "客户预留数据";
CM_ SG_ 2339700562 S2A_SUMDATA4_CUS_Reserve7_18 "客户预留数据";
CM_ SG_ 2339700562 S2A_SUMDATA4_CUS_Reserve8_18 "客户预留数据";
CM_ SG_ 2339700563 S2A_SUMDATA4_CUS_Reserve1_19 "客户预留数据";
CM_ SG_ 2339700563 S2A_SUMDATA4_CUS_Reserve2_19 "客户预留数据";
CM_ SG_ 2339700563 S2A_SUMDATA4_CUS_Reserve3_19 "客户预留数据";
CM_ SG_ 2339700563 S2A_SUMDATA4_CUS_Reserve4_19 "客户预留数据";
CM_ SG_ 2339700563 S2A_SUMDATA4_CUS_Reserve5_19 "客户预留数据";
CM_ SG_ 2339700563 S2A_SUMDATA4_CUS_Reserve6_19 "客户预留数据";
CM_ SG_ 2339700563 S2A_SUMDATA4_CUS_Reserve7_19 "客户预留数据";
CM_ SG_ 2339700563 S2A_SUMDATA4_CUS_Reserve8_19 "客户预留数据";
CM_ SG_ 2339700564 S2A_SUMDATA4_CUS_Reserve1_20 "客户预留数据";
CM_ SG_ 2339700564 S2A_SUMDATA4_CUS_Reserve2_20 "客户预留数据";
CM_ SG_ 2339700564 S2A_SUMDATA4_CUS_Reserve3_20 "客户预留数据";
CM_ SG_ 2339700564 S2A_SUMDATA4_CUS_Reserve4_20 "客户预留数据";
CM_ SG_ 2339700564 S2A_SUMDATA4_CUS_Reserve5_20 "客户预留数据";
CM_ SG_ 2339700564 S2A_SUMDATA4_CUS_Reserve6_20 "客户预留数据";
CM_ SG_ 2339700564 S2A_SUMDATA4_CUS_Reserve7_20 "客户预留数据";
CM_ SG_ 2339700564 S2A_SUMDATA4_CUS_Reserve8_20 "客户预留数据";
CM_ SG_ 2339700565 S2A_SUMDATA4_CUS_Reserve1_21 "客户预留数据";
CM_ SG_ 2339700565 S2A_SUMDATA4_CUS_Reserve2_21 "客户预留数据";
CM_ SG_ 2339700565 S2A_SUMDATA4_CUS_Reserve3_21 "客户预留数据";
CM_ SG_ 2339700565 S2A_SUMDATA4_CUS_Reserve4_21 "客户预留数据";
CM_ SG_ 2339700565 S2A_SUMDATA4_CUS_Reserve5_21 "客户预留数据";
CM_ SG_ 2339700565 S2A_SUMDATA4_CUS_Reserve6_21 "客户预留数据";
CM_ SG_ 2339700565 S2A_SUMDATA4_CUS_Reserve7_21 "客户预留数据";
CM_ SG_ 2339700565 S2A_SUMDATA4_CUS_Reserve8_21 "客户预留数据";
CM_ SG_ 2339700566 S2A_SUMDATA4_CUS_Reserve1_22 "客户预留数据";
CM_ SG_ 2339700566 S2A_SUMDATA4_CUS_Reserve2_22 "客户预留数据";
CM_ SG_ 2339700566 S2A_SUMDATA4_CUS_Reserve3_22 "客户预留数据";
CM_ SG_ 2339700566 S2A_SUMDATA4_CUS_Reserve4_22 "客户预留数据";
CM_ SG_ 2339700566 S2A_SUMDATA4_CUS_Reserve5_22 "客户预留数据";
CM_ SG_ 2339700566 S2A_SUMDATA4_CUS_Reserve6_22 "客户预留数据";
CM_ SG_ 2339700566 S2A_SUMDATA4_CUS_Reserve7_22 "客户预留数据";
CM_ SG_ 2339700566 S2A_SUMDATA4_CUS_Reserve8_22 "客户预留数据";
CM_ SG_ 2339700567 S2A_SUMDATA4_CUS_Reserve1_23 "客户预留数据";
CM_ SG_ 2339700567 S2A_SUMDATA4_CUS_Reserve2_23 "客户预留数据";
CM_ SG_ 2339700567 S2A_SUMDATA4_CUS_Reserve3_23 "客户预留数据";
CM_ SG_ 2339700567 S2A_SUMDATA4_CUS_Reserve4_23 "客户预留数据";
CM_ SG_ 2339700567 S2A_SUMDATA4_CUS_Reserve5_23 "客户预留数据";
CM_ SG_ 2339700567 S2A_SUMDATA4_CUS_Reserve6_23 "客户预留数据";
CM_ SG_ 2339700567 S2A_SUMDATA4_CUS_Reserve7_23 "客户预留数据";
CM_ SG_ 2339700567 S2A_SUMDATA4_CUS_Reserve8_23 "客户预留数据";
CM_ SG_ 2339700568 S2A_SUMDATA4_CUS_Reserve1_24 "客户预留数据";
CM_ SG_ 2339700568 S2A_SUMDATA4_CUS_Reserve2_24 "客户预留数据";
CM_ SG_ 2339700568 S2A_SUMDATA4_CUS_Reserve3_24 "客户预留数据";
CM_ SG_ 2339700568 S2A_SUMDATA4_CUS_Reserve4_24 "客户预留数据";
CM_ SG_ 2339700568 S2A_SUMDATA4_CUS_Reserve5_24 "客户预留数据";
CM_ SG_ 2339700568 S2A_SUMDATA4_CUS_Reserve6_24 "客户预留数据";
CM_ SG_ 2339700568 S2A_SUMDATA4_CUS_Reserve7_24 "客户预留数据";
CM_ SG_ 2339700568 S2A_SUMDATA4_CUS_Reserve8_24 "客户预留数据";
CM_ SG_ 2339700569 S2A_SUMDATA4_CUS_Reserve1_25 "客户预留数据";
CM_ SG_ 2339700569 S2A_SUMDATA4_CUS_Reserve2_25 "客户预留数据";
CM_ SG_ 2339700569 S2A_SUMDATA4_CUS_Reserve3_25 "客户预留数据";
CM_ SG_ 2339700569 S2A_SUMDATA4_CUS_Reserve4_25 "客户预留数据";
CM_ SG_ 2339700569 S2A_SUMDATA4_CUS_Reserve5_25 "客户预留数据";
CM_ SG_ 2339700569 S2A_SUMDATA4_CUS_Reserve6_25 "客户预留数据";
CM_ SG_ 2339700569 S2A_SUMDATA4_CUS_Reserve7_25 "客户预留数据";
CM_ SG_ 2339700569 S2A_SUMDATA4_CUS_Reserve8_25 "客户预留数据";
CM_ SG_ 2339700570 S2A_SUMDATA4_CUS_Reserve1_26 "客户预留数据";
CM_ SG_ 2339700570 S2A_SUMDATA4_CUS_Reserve2_26 "客户预留数据";
CM_ SG_ 2339700570 S2A_SUMDATA4_CUS_Reserve3_26 "客户预留数据";
CM_ SG_ 2339700570 S2A_SUMDATA4_CUS_Reserve4_26 "客户预留数据";
CM_ SG_ 2339700570 S2A_SUMDATA4_CUS_Reserve5_26 "客户预留数据";
CM_ SG_ 2339700570 S2A_SUMDATA4_CUS_Reserve6_26 "客户预留数据";
CM_ SG_ 2339700570 S2A_SUMDATA4_CUS_Reserve7_26 "客户预留数据";
CM_ SG_ 2339700570 S2A_SUMDATA4_CUS_Reserve8_26 "客户预留数据";
CM_ SG_ 2339700571 S2A_SUMDATA4_CUS_Reserve1_27 "客户预留数据";
CM_ SG_ 2339700571 S2A_SUMDATA4_CUS_Reserve2_27 "客户预留数据";
CM_ SG_ 2339700571 S2A_SUMDATA4_CUS_Reserve3_27 "客户预留数据";
CM_ SG_ 2339700571 S2A_SUMDATA4_CUS_Reserve4_27 "客户预留数据";
CM_ SG_ 2339700571 S2A_SUMDATA4_CUS_Reserve5_27 "客户预留数据";
CM_ SG_ 2339700571 S2A_SUMDATA4_CUS_Reserve6_27 "客户预留数据";
CM_ SG_ 2339700571 S2A_SUMDATA4_CUS_Reserve7_27 "客户预留数据";
CM_ SG_ 2339700571 S2A_SUMDATA4_CUS_Reserve8_27 "客户预留数据";
CM_ SG_ 2339700572 S2A_SUMDATA4_CUS_Reserve1_28 "客户预留数据";
CM_ SG_ 2339700572 S2A_SUMDATA4_CUS_Reserve2_28 "客户预留数据";
CM_ SG_ 2339700572 S2A_SUMDATA4_CUS_Reserve3_28 "客户预留数据";
CM_ SG_ 2339700572 S2A_SUMDATA4_CUS_Reserve4_28 "客户预留数据";
CM_ SG_ 2339700572 S2A_SUMDATA4_CUS_Reserve5_28 "客户预留数据";
CM_ SG_ 2339700572 S2A_SUMDATA4_CUS_Reserve6_28 "客户预留数据";
CM_ SG_ 2339700572 S2A_SUMDATA4_CUS_Reserve7_28 "客户预留数据";
CM_ SG_ 2339700572 S2A_SUMDATA4_CUS_Reserve8_28 "客户预留数据";
CM_ SG_ 2339700573 S2A_SUMDATA4_CUS_Reserve1_29 "客户预留数据";
CM_ SG_ 2339700573 S2A_SUMDATA4_CUS_Reserve2_29 "客户预留数据";
CM_ SG_ 2339700573 S2A_SUMDATA4_CUS_Reserve3_29 "客户预留数据";
CM_ SG_ 2339700573 S2A_SUMDATA4_CUS_Reserve4_29 "客户预留数据";
CM_ SG_ 2339700573 S2A_SUMDATA4_CUS_Reserve5_29 "客户预留数据";
CM_ SG_ 2339700573 S2A_SUMDATA4_CUS_Reserve6_29 "客户预留数据";
CM_ SG_ 2339700573 S2A_SUMDATA4_CUS_Reserve7_29 "客户预留数据";
CM_ SG_ 2339700573 S2A_SUMDATA4_CUS_Reserve8_29 "客户预留数据";
CM_ SG_ 2339700574 S2A_SUMDATA4_CUS_Reserve1_30 "客户预留数据";
CM_ SG_ 2339700574 S2A_SUMDATA4_CUS_Reserve2_30 "客户预留数据";
CM_ SG_ 2339700574 S2A_SUMDATA4_CUS_Reserve3_30 "客户预留数据";
CM_ SG_ 2339700574 S2A_SUMDATA4_CUS_Reserve4_30 "客户预留数据";
CM_ SG_ 2339700574 S2A_SUMDATA4_CUS_Reserve5_30 "客户预留数据";
CM_ SG_ 2339700574 S2A_SUMDATA4_CUS_Reserve6_30 "客户预留数据";
CM_ SG_ 2339700574 S2A_SUMDATA4_CUS_Reserve7_30 "客户预留数据";
CM_ SG_ 2339700574 S2A_SUMDATA4_CUS_Reserve8_30 "客户预留数据";
CM_ SG_ 2339700575 S2A_SUMDATA4_CUS_Reserve1_31 "客户预留数据";
CM_ SG_ 2339700575 S2A_SUMDATA4_CUS_Reserve2_31 "客户预留数据";
CM_ SG_ 2339700575 S2A_SUMDATA4_CUS_Reserve3_31 "客户预留数据";
CM_ SG_ 2339700575 S2A_SUMDATA4_CUS_Reserve4_31 "客户预留数据";
CM_ SG_ 2339700575 S2A_SUMDATA4_CUS_Reserve5_31 "客户预留数据";
CM_ SG_ 2339700575 S2A_SUMDATA4_CUS_Reserve6_31 "客户预留数据";
CM_ SG_ 2339700575 S2A_SUMDATA4_CUS_Reserve7_31 "客户预留数据";
CM_ SG_ 2339700575 S2A_SUMDATA4_CUS_Reserve8_31 "客户预留数据";
CM_ SG_ 2339700576 S2A_SUMDATA4_CUS_Reserve1_32 "客户预留数据";
CM_ SG_ 2339700576 S2A_SUMDATA4_CUS_Reserve2_32 "客户预留数据";
CM_ SG_ 2339700576 S2A_SUMDATA4_CUS_Reserve3_32 "客户预留数据";
CM_ SG_ 2339700576 S2A_SUMDATA4_CUS_Reserve4_32 "客户预留数据";
CM_ SG_ 2339700576 S2A_SUMDATA4_CUS_Reserve5_32 "客户预留数据";
CM_ SG_ 2339700576 S2A_SUMDATA4_CUS_Reserve6_32 "客户预留数据";
CM_ SG_ 2339700576 S2A_SUMDATA4_CUS_Reserve7_32 "客户预留数据";
CM_ SG_ 2339700576 S2A_SUMDATA4_CUS_Reserve8_32 "客户预留数据";
CM_ SG_ 2339700577 S2A_SUMDATA4_CUS_Reserve1_33 "客户预留数据";
CM_ SG_ 2339700577 S2A_SUMDATA4_CUS_Reserve2_33 "客户预留数据";
CM_ SG_ 2339700577 S2A_SUMDATA4_CUS_Reserve3_33 "客户预留数据";
CM_ SG_ 2339700577 S2A_SUMDATA4_CUS_Reserve4_33 "客户预留数据";
CM_ SG_ 2339700577 S2A_SUMDATA4_CUS_Reserve5_33 "客户预留数据";
CM_ SG_ 2339700577 S2A_SUMDATA4_CUS_Reserve6_33 "客户预留数据";
CM_ SG_ 2339700577 S2A_SUMDATA4_CUS_Reserve7_33 "客户预留数据";
CM_ SG_ 2339700577 S2A_SUMDATA4_CUS_Reserve8_33 "客户预留数据";
CM_ SG_ 2339700578 S2A_SUMDATA4_CUS_Reserve1_34 "客户预留数据";
CM_ SG_ 2339700578 S2A_SUMDATA4_CUS_Reserve2_34 "客户预留数据";
CM_ SG_ 2339700578 S2A_SUMDATA4_CUS_Reserve3_34 "客户预留数据";
CM_ SG_ 2339700578 S2A_SUMDATA4_CUS_Reserve4_34 "客户预留数据";
CM_ SG_ 2339700578 S2A_SUMDATA4_CUS_Reserve5_34 "客户预留数据";
CM_ SG_ 2339700578 S2A_SUMDATA4_CUS_Reserve6_34 "客户预留数据";
CM_ SG_ 2339700578 S2A_SUMDATA4_CUS_Reserve7_34 "客户预留数据";
CM_ SG_ 2339700578 S2A_SUMDATA4_CUS_Reserve8_34 "客户预留数据";
CM_ SG_ 2339700579 S2A_SUMDATA4_CUS_Reserve1_35 "客户预留数据";
CM_ SG_ 2339700579 S2A_SUMDATA4_CUS_Reserve2_35 "客户预留数据";
CM_ SG_ 2339700579 S2A_SUMDATA4_CUS_Reserve3_35 "客户预留数据";
CM_ SG_ 2339700579 S2A_SUMDATA4_CUS_Reserve4_35 "客户预留数据";
CM_ SG_ 2339700579 S2A_SUMDATA4_CUS_Reserve5_35 "客户预留数据";
CM_ SG_ 2339700579 S2A_SUMDATA4_CUS_Reserve6_35 "客户预留数据";
CM_ SG_ 2339700579 S2A_SUMDATA4_CUS_Reserve7_35 "客户预留数据";
CM_ SG_ 2339700579 S2A_SUMDATA4_CUS_Reserve8_35 "客户预留数据";
CM_ SG_ 2339700580 S2A_SUMDATA4_CUS_Reserve1_36 "客户预留数据";
CM_ SG_ 2339700580 S2A_SUMDATA4_CUS_Reserve2_36 "客户预留数据";
CM_ SG_ 2339700580 S2A_SUMDATA4_CUS_Reserve3_36 "客户预留数据";
CM_ SG_ 2339700580 S2A_SUMDATA4_CUS_Reserve4_36 "客户预留数据";
CM_ SG_ 2339700580 S2A_SUMDATA4_CUS_Reserve5_36 "客户预留数据";
CM_ SG_ 2339700580 S2A_SUMDATA4_CUS_Reserve6_36 "客户预留数据";
CM_ SG_ 2339700580 S2A_SUMDATA4_CUS_Reserve7_36 "客户预留数据";
CM_ SG_ 2339700580 S2A_SUMDATA4_CUS_Reserve8_36 "客户预留数据";
CM_ SG_ 2339700581 S2A_SUMDATA4_CUS_Reserve1_37 "客户预留数据";
CM_ SG_ 2339700581 S2A_SUMDATA4_CUS_Reserve2_37 "客户预留数据";
CM_ SG_ 2339700581 S2A_SUMDATA4_CUS_Reserve3_37 "客户预留数据";
CM_ SG_ 2339700581 S2A_SUMDATA4_CUS_Reserve4_37 "客户预留数据";
CM_ SG_ 2339700581 S2A_SUMDATA4_CUS_Reserve5_37 "客户预留数据";
CM_ SG_ 2339700581 S2A_SUMDATA4_CUS_Reserve6_37 "客户预留数据";
CM_ SG_ 2339700581 S2A_SUMDATA4_CUS_Reserve7_37 "客户预留数据";
CM_ SG_ 2339700581 S2A_SUMDATA4_CUS_Reserve8_37 "客户预留数据";
CM_ SG_ 2339700582 S2A_SUMDATA4_CUS_Reserve1_38 "客户预留数据";
CM_ SG_ 2339700582 S2A_SUMDATA4_CUS_Reserve2_38 "客户预留数据";
CM_ SG_ 2339700582 S2A_SUMDATA4_CUS_Reserve3_38 "客户预留数据";
CM_ SG_ 2339700582 S2A_SUMDATA4_CUS_Reserve4_38 "客户预留数据";
CM_ SG_ 2339700582 S2A_SUMDATA4_CUS_Reserve5_38 "客户预留数据";
CM_ SG_ 2339700582 S2A_SUMDATA4_CUS_Reserve6_38 "客户预留数据";
CM_ SG_ 2339700582 S2A_SUMDATA4_CUS_Reserve7_38 "客户预留数据";
CM_ SG_ 2339700582 S2A_SUMDATA4_CUS_Reserve8_38 "客户预留数据";
CM_ SG_ 2339700583 S2A_SUMDATA4_CUS_Reserve1_39 "客户预留数据";
CM_ SG_ 2339700583 S2A_SUMDATA4_CUS_Reserve2_39 "客户预留数据";
CM_ SG_ 2339700583 S2A_SUMDATA4_CUS_Reserve3_39 "客户预留数据";
CM_ SG_ 2339700583 S2A_SUMDATA4_CUS_Reserve4_39 "客户预留数据";
CM_ SG_ 2339700583 S2A_SUMDATA4_CUS_Reserve5_39 "客户预留数据";
CM_ SG_ 2339700583 S2A_SUMDATA4_CUS_Reserve6_39 "客户预留数据";
CM_ SG_ 2339700583 S2A_SUMDATA4_CUS_Reserve7_39 "客户预留数据";
CM_ SG_ 2339700583 S2A_SUMDATA4_CUS_Reserve8_39 "客户预留数据";
CM_ SG_ 2339700584 S2A_SUMDATA4_CUS_Reserve1_40 "客户预留数据";
CM_ SG_ 2339700584 S2A_SUMDATA4_CUS_Reserve2_40 "客户预留数据";
CM_ SG_ 2339700584 S2A_SUMDATA4_CUS_Reserve3_40 "客户预留数据";
CM_ SG_ 2339700584 S2A_SUMDATA4_CUS_Reserve4_40 "客户预留数据";
CM_ SG_ 2339700584 S2A_SUMDATA4_CUS_Reserve5_40 "客户预留数据";
CM_ SG_ 2339700584 S2A_SUMDATA4_CUS_Reserve6_40 "客户预留数据";
CM_ SG_ 2339700584 S2A_SUMDATA4_CUS_Reserve7_40 "客户预留数据";
CM_ SG_ 2339700584 S2A_SUMDATA4_CUS_Reserve8_40 "客户预留数据";
CM_ SG_ 2339700585 S2A_SUMDATA4_CUS_Reserve1_41 "客户预留数据";
CM_ SG_ 2339700585 S2A_SUMDATA4_CUS_Reserve2_41 "客户预留数据";
CM_ SG_ 2339700585 S2A_SUMDATA4_CUS_Reserve3_41 "客户预留数据";
CM_ SG_ 2339700585 S2A_SUMDATA4_CUS_Reserve4_41 "客户预留数据";
CM_ SG_ 2339700585 S2A_SUMDATA4_CUS_Reserve5_41 "客户预留数据";
CM_ SG_ 2339700585 S2A_SUMDATA4_CUS_Reserve6_41 "客户预留数据";
CM_ SG_ 2339700585 S2A_SUMDATA4_CUS_Reserve7_41 "客户预留数据";
CM_ SG_ 2339700585 S2A_SUMDATA4_CUS_Reserve8_41 "客户预留数据";
CM_ SG_ 2339700586 S2A_SUMDATA4_CUS_Reserve1_42 "客户预留数据";
CM_ SG_ 2339700586 S2A_SUMDATA4_CUS_Reserve2_42 "客户预留数据";
CM_ SG_ 2339700586 S2A_SUMDATA4_CUS_Reserve3_42 "客户预留数据";
CM_ SG_ 2339700586 S2A_SUMDATA4_CUS_Reserve4_42 "客户预留数据";
CM_ SG_ 2339700586 S2A_SUMDATA4_CUS_Reserve5_42 "客户预留数据";
CM_ SG_ 2339700586 S2A_SUMDATA4_CUS_Reserve6_42 "客户预留数据";
CM_ SG_ 2339700586 S2A_SUMDATA4_CUS_Reserve7_42 "客户预留数据";
CM_ SG_ 2339700586 S2A_SUMDATA4_CUS_Reserve8_42 "客户预留数据";
CM_ SG_ 2339700587 S2A_SUMDATA4_CUS_Reserve1_43 "客户预留数据";
CM_ SG_ 2339700587 S2A_SUMDATA4_CUS_Reserve2_43 "客户预留数据";
CM_ SG_ 2339700587 S2A_SUMDATA4_CUS_Reserve3_43 "客户预留数据";
CM_ SG_ 2339700587 S2A_SUMDATA4_CUS_Reserve4_43 "客户预留数据";
CM_ SG_ 2339700587 S2A_SUMDATA4_CUS_Reserve5_43 "客户预留数据";
CM_ SG_ 2339700587 S2A_SUMDATA4_CUS_Reserve6_43 "客户预留数据";
CM_ SG_ 2339700587 S2A_SUMDATA4_CUS_Reserve7_43 "客户预留数据";
CM_ SG_ 2339700587 S2A_SUMDATA4_CUS_Reserve8_43 "客户预留数据";
CM_ SG_ 2339700588 S2A_SUMDATA4_CUS_Reserve1_44 "客户预留数据";
CM_ SG_ 2339700588 S2A_SUMDATA4_CUS_Reserve2_44 "客户预留数据";
CM_ SG_ 2339700588 S2A_SUMDATA4_CUS_Reserve3_44 "客户预留数据";
CM_ SG_ 2339700588 S2A_SUMDATA4_CUS_Reserve4_44 "客户预留数据";
CM_ SG_ 2339700588 S2A_SUMDATA4_CUS_Reserve5_44 "客户预留数据";
CM_ SG_ 2339700588 S2A_SUMDATA4_CUS_Reserve6_44 "客户预留数据";
CM_ SG_ 2339700588 S2A_SUMDATA4_CUS_Reserve7_44 "客户预留数据";
CM_ SG_ 2339700588 S2A_SUMDATA4_CUS_Reserve8_44 "客户预留数据";
CM_ SG_ 2339700589 S2A_SUMDATA4_CUS_Reserve1_45 "客户预留数据";
CM_ SG_ 2339700589 S2A_SUMDATA4_CUS_Reserve2_45 "客户预留数据";
CM_ SG_ 2339700589 S2A_SUMDATA4_CUS_Reserve3_45 "客户预留数据";
CM_ SG_ 2339700589 S2A_SUMDATA4_CUS_Reserve4_45 "客户预留数据";
CM_ SG_ 2339700589 S2A_SUMDATA4_CUS_Reserve5_45 "客户预留数据";
CM_ SG_ 2339700589 S2A_SUMDATA4_CUS_Reserve6_45 "客户预留数据";
CM_ SG_ 2339700589 S2A_SUMDATA4_CUS_Reserve7_45 "客户预留数据";
CM_ SG_ 2339700589 S2A_SUMDATA4_CUS_Reserve8_45 "客户预留数据";
CM_ SG_ 2339700590 S2A_SUMDATA4_CUS_Reserve1_46 "客户预留数据";
CM_ SG_ 2339700590 S2A_SUMDATA4_CUS_Reserve2_46 "客户预留数据";
CM_ SG_ 2339700590 S2A_SUMDATA4_CUS_Reserve3_46 "客户预留数据";
CM_ SG_ 2339700590 S2A_SUMDATA4_CUS_Reserve4_46 "客户预留数据";
CM_ SG_ 2339700590 S2A_SUMDATA4_CUS_Reserve5_46 "客户预留数据";
CM_ SG_ 2339700590 S2A_SUMDATA4_CUS_Reserve6_46 "客户预留数据";
CM_ SG_ 2339700590 S2A_SUMDATA4_CUS_Reserve7_46 "客户预留数据";
CM_ SG_ 2339700590 S2A_SUMDATA4_CUS_Reserve8_46 "客户预留数据";
CM_ SG_ 2339700591 S2A_SUMDATA4_CUS_Reserve1_47 "客户预留数据";
CM_ SG_ 2339700591 S2A_SUMDATA4_CUS_Reserve2_47 "客户预留数据";
CM_ SG_ 2339700591 S2A_SUMDATA4_CUS_Reserve3_47 "客户预留数据";
CM_ SG_ 2339700591 S2A_SUMDATA4_CUS_Reserve4_47 "客户预留数据";
CM_ SG_ 2339700591 S2A_SUMDATA4_CUS_Reserve5_47 "客户预留数据";
CM_ SG_ 2339700591 S2A_SUMDATA4_CUS_Reserve6_47 "客户预留数据";
CM_ SG_ 2339700591 S2A_SUMDATA4_CUS_Reserve7_47 "客户预留数据";
CM_ SG_ 2339700591 S2A_SUMDATA4_CUS_Reserve8_47 "客户预留数据";
CM_ SG_ 2339700592 S2A_SUMDATA4_CUS_Reserve1_48 "客户预留数据";
CM_ SG_ 2339700592 S2A_SUMDATA4_CUS_Reserve2_48 "客户预留数据";
CM_ SG_ 2339700592 S2A_SUMDATA4_CUS_Reserve3_48 "客户预留数据";
CM_ SG_ 2339700592 S2A_SUMDATA4_CUS_Reserve4_48 "客户预留数据";
CM_ SG_ 2339700592 S2A_SUMDATA4_CUS_Reserve5_48 "客户预留数据";
CM_ SG_ 2339700592 S2A_SUMDATA4_CUS_Reserve6_48 "客户预留数据";
CM_ SG_ 2339700592 S2A_SUMDATA4_CUS_Reserve7_48 "客户预留数据";
CM_ SG_ 2339700592 S2A_SUMDATA4_CUS_Reserve8_48 "客户预留数据";
CM_ SG_ 2339700593 S2A_SUMDATA4_CUS_Reserve1_49 "客户预留数据";
CM_ SG_ 2339700593 S2A_SUMDATA4_CUS_Reserve2_49 "客户预留数据";
CM_ SG_ 2339700593 S2A_SUMDATA4_CUS_Reserve3_49 "客户预留数据";
CM_ SG_ 2339700593 S2A_SUMDATA4_CUS_Reserve4_49 "客户预留数据";
CM_ SG_ 2339700593 S2A_SUMDATA4_CUS_Reserve5_49 "客户预留数据";
CM_ SG_ 2339700593 S2A_SUMDATA4_CUS_Reserve6_49 "客户预留数据";
CM_ SG_ 2339700593 S2A_SUMDATA4_CUS_Reserve7_49 "客户预留数据";
CM_ SG_ 2339700593 S2A_SUMDATA4_CUS_Reserve8_49 "客户预留数据";
CM_ SG_ 2339700594 S2A_SUMDATA4_CUS_Reserve1_50 "客户预留数据";
CM_ SG_ 2339700594 S2A_SUMDATA4_CUS_Reserve2_50 "客户预留数据";
CM_ SG_ 2339700594 S2A_SUMDATA4_CUS_Reserve3_50 "客户预留数据";
CM_ SG_ 2339700594 S2A_SUMDATA4_CUS_Reserve4_50 "客户预留数据";
CM_ SG_ 2339700594 S2A_SUMDATA4_CUS_Reserve5_50 "客户预留数据";
CM_ SG_ 2339700594 S2A_SUMDATA4_CUS_Reserve6_50 "客户预留数据";
CM_ SG_ 2339700594 S2A_SUMDATA4_CUS_Reserve7_50 "客户预留数据";
CM_ SG_ 2339700594 S2A_SUMDATA4_CUS_Reserve8_50 "客户预留数据";
CM_ SG_ 2339700595 S2A_SUMDATA4_CUS_Reserve1_51 "客户预留数据";
CM_ SG_ 2339700595 S2A_SUMDATA4_CUS_Reserve2_51 "客户预留数据";
CM_ SG_ 2339700595 S2A_SUMDATA4_CUS_Reserve3_51 "客户预留数据";
CM_ SG_ 2339700595 S2A_SUMDATA4_CUS_Reserve4_51 "客户预留数据";
CM_ SG_ 2339700595 S2A_SUMDATA4_CUS_Reserve5_51 "客户预留数据";
CM_ SG_ 2339700595 S2A_SUMDATA4_CUS_Reserve6_51 "客户预留数据";
CM_ SG_ 2339700595 S2A_SUMDATA4_CUS_Reserve7_51 "客户预留数据";
CM_ SG_ 2339700595 S2A_SUMDATA4_CUS_Reserve8_51 "客户预留数据";
CM_ SG_ 2339700596 S2A_SUMDATA4_CUS_Reserve1_52 "客户预留数据";
CM_ SG_ 2339700596 S2A_SUMDATA4_CUS_Reserve2_52 "客户预留数据";
CM_ SG_ 2339700596 S2A_SUMDATA4_CUS_Reserve3_52 "客户预留数据";
CM_ SG_ 2339700596 S2A_SUMDATA4_CUS_Reserve4_52 "客户预留数据";
CM_ SG_ 2339700596 S2A_SUMDATA4_CUS_Reserve5_52 "客户预留数据";
CM_ SG_ 2339700596 S2A_SUMDATA4_CUS_Reserve6_52 "客户预留数据";
CM_ SG_ 2339700596 S2A_SUMDATA4_CUS_Reserve7_52 "客户预留数据";
CM_ SG_ 2339700596 S2A_SUMDATA4_CUS_Reserve8_52 "客户预留数据";
CM_ SG_ 2339700597 S2A_SUMDATA4_CUS_Reserve1_53 "客户预留数据";
CM_ SG_ 2339700597 S2A_SUMDATA4_CUS_Reserve2_53 "客户预留数据";
CM_ SG_ 2339700597 S2A_SUMDATA4_CUS_Reserve3_53 "客户预留数据";
CM_ SG_ 2339700597 S2A_SUMDATA4_CUS_Reserve4_53 "客户预留数据";
CM_ SG_ 2339700597 S2A_SUMDATA4_CUS_Reserve5_53 "客户预留数据";
CM_ SG_ 2339700597 S2A_SUMDATA4_CUS_Reserve6_53 "客户预留数据";
CM_ SG_ 2339700597 S2A_SUMDATA4_CUS_Reserve7_53 "客户预留数据";
CM_ SG_ 2339700597 S2A_SUMDATA4_CUS_Reserve8_53 "客户预留数据";
CM_ SG_ 2339700598 S2A_SUMDATA4_CUS_Reserve1_54 "客户预留数据";
CM_ SG_ 2339700598 S2A_SUMDATA4_CUS_Reserve2_54 "客户预留数据";
CM_ SG_ 2339700598 S2A_SUMDATA4_CUS_Reserve3_54 "客户预留数据";
CM_ SG_ 2339700598 S2A_SUMDATA4_CUS_Reserve4_54 "客户预留数据";
CM_ SG_ 2339700598 S2A_SUMDATA4_CUS_Reserve5_54 "客户预留数据";
CM_ SG_ 2339700598 S2A_SUMDATA4_CUS_Reserve6_54 "客户预留数据";
CM_ SG_ 2339700598 S2A_SUMDATA4_CUS_Reserve7_54 "客户预留数据";
CM_ SG_ 2339700598 S2A_SUMDATA4_CUS_Reserve8_54 "客户预留数据";
CM_ SG_ 2339700599 S2A_SUMDATA4_CUS_Reserve1_55 "客户预留数据";
CM_ SG_ 2339700599 S2A_SUMDATA4_CUS_Reserve2_55 "客户预留数据";
CM_ SG_ 2339700599 S2A_SUMDATA4_CUS_Reserve3_55 "客户预留数据";
CM_ SG_ 2339700599 S2A_SUMDATA4_CUS_Reserve4_55 "客户预留数据";
CM_ SG_ 2339700599 S2A_SUMDATA4_CUS_Reserve5_55 "客户预留数据";
CM_ SG_ 2339700599 S2A_SUMDATA4_CUS_Reserve6_55 "客户预留数据";
CM_ SG_ 2339700599 S2A_SUMDATA4_CUS_Reserve7_55 "客户预留数据";
CM_ SG_ 2339700599 S2A_SUMDATA4_CUS_Reserve8_55 "客户预留数据";
CM_ SG_ 2339700600 S2A_SUMDATA4_CUS_Reserve1_56 "客户预留数据";
CM_ SG_ 2339700600 S2A_SUMDATA4_CUS_Reserve2_56 "客户预留数据";
CM_ SG_ 2339700600 S2A_SUMDATA4_CUS_Reserve3_56 "客户预留数据";
CM_ SG_ 2339700600 S2A_SUMDATA4_CUS_Reserve4_56 "客户预留数据";
CM_ SG_ 2339700600 S2A_SUMDATA4_CUS_Reserve5_56 "客户预留数据";
CM_ SG_ 2339700600 S2A_SUMDATA4_CUS_Reserve6_56 "客户预留数据";
CM_ SG_ 2339700600 S2A_SUMDATA4_CUS_Reserve7_56 "客户预留数据";
CM_ SG_ 2339700600 S2A_SUMDATA4_CUS_Reserve8_56 "客户预留数据";
CM_ SG_ 2339700601 S2A_SUMDATA4_CUS_Reserve1_57 "客户预留数据";
CM_ SG_ 2339700601 S2A_SUMDATA4_CUS_Reserve2_57 "客户预留数据";
CM_ SG_ 2339700601 S2A_SUMDATA4_CUS_Reserve3_57 "客户预留数据";
CM_ SG_ 2339700601 S2A_SUMDATA4_CUS_Reserve4_57 "客户预留数据";
CM_ SG_ 2339700601 S2A_SUMDATA4_CUS_Reserve5_57 "客户预留数据";
CM_ SG_ 2339700601 S2A_SUMDATA4_CUS_Reserve6_57 "客户预留数据";
CM_ SG_ 2339700601 S2A_SUMDATA4_CUS_Reserve7_57 "客户预留数据";
CM_ SG_ 2339700601 S2A_SUMDATA4_CUS_Reserve8_57 "客户预留数据";
CM_ SG_ 2339700602 S2A_SUMDATA4_CUS_Reserve1_58 "客户预留数据";
CM_ SG_ 2339700602 S2A_SUMDATA4_CUS_Reserve2_58 "客户预留数据";
CM_ SG_ 2339700602 S2A_SUMDATA4_CUS_Reserve3_58 "客户预留数据";
CM_ SG_ 2339700602 S2A_SUMDATA4_CUS_Reserve4_58 "客户预留数据";
CM_ SG_ 2339700602 S2A_SUMDATA4_CUS_Reserve5_58 "客户预留数据";
CM_ SG_ 2339700602 S2A_SUMDATA4_CUS_Reserve6_58 "客户预留数据";
CM_ SG_ 2339700602 S2A_SUMDATA4_CUS_Reserve7_58 "客户预留数据";
CM_ SG_ 2339700602 S2A_SUMDATA4_CUS_Reserve8_58 "客户预留数据";
CM_ SG_ 2339700603 S2A_SUMDATA4_CUS_Reserve1_59 "客户预留数据";
CM_ SG_ 2339700603 S2A_SUMDATA4_CUS_Reserve2_59 "客户预留数据";
CM_ SG_ 2339700603 S2A_SUMDATA4_CUS_Reserve3_59 "客户预留数据";
CM_ SG_ 2339700603 S2A_SUMDATA4_CUS_Reserve4_59 "客户预留数据";
CM_ SG_ 2339700603 S2A_SUMDATA4_CUS_Reserve5_59 "客户预留数据";
CM_ SG_ 2339700603 S2A_SUMDATA4_CUS_Reserve6_59 "客户预留数据";
CM_ SG_ 2339700603 S2A_SUMDATA4_CUS_Reserve7_59 "客户预留数据";
CM_ SG_ 2339700603 S2A_SUMDATA4_CUS_Reserve8_59 "客户预留数据";
CM_ SG_ 2339700604 S2A_SUMDATA4_CUS_Reserve1_60 "客户预留数据";
CM_ SG_ 2339700604 S2A_SUMDATA4_CUS_Reserve2_60 "客户预留数据";
CM_ SG_ 2339700604 S2A_SUMDATA4_CUS_Reserve3_60 "客户预留数据";
CM_ SG_ 2339700604 S2A_SUMDATA4_CUS_Reserve4_60 "客户预留数据";
CM_ SG_ 2339700604 S2A_SUMDATA4_CUS_Reserve5_60 "客户预留数据";
CM_ SG_ 2339700604 S2A_SUMDATA4_CUS_Reserve6_60 "客户预留数据";
CM_ SG_ 2339700604 S2A_SUMDATA4_CUS_Reserve7_60 "客户预留数据";
CM_ SG_ 2339700604 S2A_SUMDATA4_CUS_Reserve8_60 "客户预留数据";
CM_ SG_ 2339700605 S2A_SUMDATA4_CUS_Reserve1_61 "客户预留数据";
CM_ SG_ 2339700605 S2A_SUMDATA4_CUS_Reserve2_61 "客户预留数据";
CM_ SG_ 2339700605 S2A_SUMDATA4_CUS_Reserve3_61 "客户预留数据";
CM_ SG_ 2339700605 S2A_SUMDATA4_CUS_Reserve4_61 "客户预留数据";
CM_ SG_ 2339700605 S2A_SUMDATA4_CUS_Reserve5_61 "客户预留数据";
CM_ SG_ 2339700605 S2A_SUMDATA4_CUS_Reserve6_61 "客户预留数据";
CM_ SG_ 2339700605 S2A_SUMDATA4_CUS_Reserve7_61 "客户预留数据";
CM_ SG_ 2339700605 S2A_SUMDATA4_CUS_Reserve8_61 "客户预留数据";
CM_ SG_ 2339700606 S2A_SUMDATA4_CUS_Reserve1_62 "客户预留数据";
CM_ SG_ 2339700606 S2A_SUMDATA4_CUS_Reserve2_62 "客户预留数据";
CM_ SG_ 2339700606 S2A_SUMDATA4_CUS_Reserve3_62 "客户预留数据";
CM_ SG_ 2339700606 S2A_SUMDATA4_CUS_Reserve4_62 "客户预留数据";
CM_ SG_ 2339700606 S2A_SUMDATA4_CUS_Reserve5_62 "客户预留数据";
CM_ SG_ 2339700606 S2A_SUMDATA4_CUS_Reserve6_62 "客户预留数据";
CM_ SG_ 2339700606 S2A_SUMDATA4_CUS_Reserve7_62 "客户预留数据";
CM_ SG_ 2339700606 S2A_SUMDATA4_CUS_Reserve8_62 "客户预留数据";
CM_ SG_ 2339700607 S2A_SUMDATA4_CUS_Reserve1_63 "客户预留数据";
CM_ SG_ 2339700607 S2A_SUMDATA4_CUS_Reserve2_63 "客户预留数据";
CM_ SG_ 2339700607 S2A_SUMDATA4_CUS_Reserve3_63 "客户预留数据";
CM_ SG_ 2339700607 S2A_SUMDATA4_CUS_Reserve4_63 "客户预留数据";
CM_ SG_ 2339700607 S2A_SUMDATA4_CUS_Reserve5_63 "客户预留数据";
CM_ SG_ 2339700607 S2A_SUMDATA4_CUS_Reserve6_63 "客户预留数据";
CM_ SG_ 2339700607 S2A_SUMDATA4_CUS_Reserve7_63 "客户预留数据";
CM_ SG_ 2339700607 S2A_SUMDATA4_CUS_Reserve8_63 "客户预留数据";
CM_ SG_ 2339766081 S2A_SUMDATA5_CUS_Reserve1_01 "客户预留数据";
CM_ SG_ 2339766081 S2A_SUMDATA5_CUS_Reserve2_01 "客户预留数据";
CM_ SG_ 2339766081 S2A_SUMDATA5_CUS_Reserve3_01 "客户预留数据";
CM_ SG_ 2339766081 S2A_SUMDATA5_CUS_Reserve4_01 "客户预留数据";
CM_ SG_ 2339766081 S2A_SUMDATA5_CUS_Reserve5_01 "客户预留数据";
CM_ SG_ 2339766081 S2A_SUMDATA5_CUS_Reserve6_01 "客户预留数据";
CM_ SG_ 2339766081 S2A_SUMDATA5_CUS_Reserve7_01 "客户预留数据";
CM_ SG_ 2339766081 S2A_SUMDATA5_CUS_Reserve8_01 "客户预留数据";
CM_ SG_ 2339766082 S2A_SUMDATA5_CUS_Reserve1_02 "客户预留数据";
CM_ SG_ 2339766082 S2A_SUMDATA5_CUS_Reserve2_02 "客户预留数据";
CM_ SG_ 2339766082 S2A_SUMDATA5_CUS_Reserve3_02 "客户预留数据";
CM_ SG_ 2339766082 S2A_SUMDATA5_CUS_Reserve4_02 "客户预留数据";
CM_ SG_ 2339766082 S2A_SUMDATA5_CUS_Reserve5_02 "客户预留数据";
CM_ SG_ 2339766082 S2A_SUMDATA5_CUS_Reserve6_02 "客户预留数据";
CM_ SG_ 2339766082 S2A_SUMDATA5_CUS_Reserve7_02 "客户预留数据";
CM_ SG_ 2339766082 S2A_SUMDATA5_CUS_Reserve8_02 "客户预留数据";
CM_ SG_ 2339766083 S2A_SUMDATA5_CUS_Reserve1_03 "客户预留数据";
CM_ SG_ 2339766083 S2A_SUMDATA5_CUS_Reserve2_03 "客户预留数据";
CM_ SG_ 2339766083 S2A_SUMDATA5_CUS_Reserve3_03 "客户预留数据";
CM_ SG_ 2339766083 S2A_SUMDATA5_CUS_Reserve4_03 "客户预留数据";
CM_ SG_ 2339766083 S2A_SUMDATA5_CUS_Reserve5_03 "客户预留数据";
CM_ SG_ 2339766083 S2A_SUMDATA5_CUS_Reserve6_03 "客户预留数据";
CM_ SG_ 2339766083 S2A_SUMDATA5_CUS_Reserve7_03 "客户预留数据";
CM_ SG_ 2339766083 S2A_SUMDATA5_CUS_Reserve8_03 "客户预留数据";
CM_ SG_ 2339766084 S2A_SUMDATA5_CUS_Reserve1_04 "客户预留数据";
CM_ SG_ 2339766084 S2A_SUMDATA5_CUS_Reserve2_04 "客户预留数据";
CM_ SG_ 2339766084 S2A_SUMDATA5_CUS_Reserve3_04 "客户预留数据";
CM_ SG_ 2339766084 S2A_SUMDATA5_CUS_Reserve4_04 "客户预留数据";
CM_ SG_ 2339766084 S2A_SUMDATA5_CUS_Reserve5_04 "客户预留数据";
CM_ SG_ 2339766084 S2A_SUMDATA5_CUS_Reserve6_04 "客户预留数据";
CM_ SG_ 2339766084 S2A_SUMDATA5_CUS_Reserve7_04 "客户预留数据";
CM_ SG_ 2339766084 S2A_SUMDATA5_CUS_Reserve8_04 "客户预留数据";
CM_ SG_ 2339766085 S2A_SUMDATA5_CUS_Reserve1_05 "客户预留数据";
CM_ SG_ 2339766085 S2A_SUMDATA5_CUS_Reserve2_05 "客户预留数据";
CM_ SG_ 2339766085 S2A_SUMDATA5_CUS_Reserve3_05 "客户预留数据";
CM_ SG_ 2339766085 S2A_SUMDATA5_CUS_Reserve4_05 "客户预留数据";
CM_ SG_ 2339766085 S2A_SUMDATA5_CUS_Reserve5_05 "客户预留数据";
CM_ SG_ 2339766085 S2A_SUMDATA5_CUS_Reserve6_05 "客户预留数据";
CM_ SG_ 2339766085 S2A_SUMDATA5_CUS_Reserve7_05 "客户预留数据";
CM_ SG_ 2339766085 S2A_SUMDATA5_CUS_Reserve8_05 "客户预留数据";
CM_ SG_ 2339766086 S2A_SUMDATA5_CUS_Reserve1_06 "客户预留数据";
CM_ SG_ 2339766086 S2A_SUMDATA5_CUS_Reserve2_06 "客户预留数据";
CM_ SG_ 2339766086 S2A_SUMDATA5_CUS_Reserve3_06 "客户预留数据";
CM_ SG_ 2339766086 S2A_SUMDATA5_CUS_Reserve4_06 "客户预留数据";
CM_ SG_ 2339766086 S2A_SUMDATA5_CUS_Reserve5_06 "客户预留数据";
CM_ SG_ 2339766086 S2A_SUMDATA5_CUS_Reserve6_06 "客户预留数据";
CM_ SG_ 2339766086 S2A_SUMDATA5_CUS_Reserve7_06 "客户预留数据";
CM_ SG_ 2339766086 S2A_SUMDATA5_CUS_Reserve8_06 "客户预留数据";
CM_ SG_ 2339766087 S2A_SUMDATA5_CUS_Reserve1_07 "客户预留数据";
CM_ SG_ 2339766087 S2A_SUMDATA5_CUS_Reserve2_07 "客户预留数据";
CM_ SG_ 2339766087 S2A_SUMDATA5_CUS_Reserve3_07 "客户预留数据";
CM_ SG_ 2339766087 S2A_SUMDATA5_CUS_Reserve4_07 "客户预留数据";
CM_ SG_ 2339766087 S2A_SUMDATA5_CUS_Reserve5_07 "客户预留数据";
CM_ SG_ 2339766087 S2A_SUMDATA5_CUS_Reserve6_07 "客户预留数据";
CM_ SG_ 2339766087 S2A_SUMDATA5_CUS_Reserve7_07 "客户预留数据";
CM_ SG_ 2339766087 S2A_SUMDATA5_CUS_Reserve8_07 "客户预留数据";
CM_ SG_ 2339766088 S2A_SUMDATA5_CUS_Reserve1_08 "客户预留数据";
CM_ SG_ 2339766088 S2A_SUMDATA5_CUS_Reserve2_08 "客户预留数据";
CM_ SG_ 2339766088 S2A_SUMDATA5_CUS_Reserve3_08 "客户预留数据";
CM_ SG_ 2339766088 S2A_SUMDATA5_CUS_Reserve4_08 "客户预留数据";
CM_ SG_ 2339766088 S2A_SUMDATA5_CUS_Reserve5_08 "客户预留数据";
CM_ SG_ 2339766088 S2A_SUMDATA5_CUS_Reserve6_08 "客户预留数据";
CM_ SG_ 2339766088 S2A_SUMDATA5_CUS_Reserve7_08 "客户预留数据";
CM_ SG_ 2339766088 S2A_SUMDATA5_CUS_Reserve8_08 "客户预留数据";
CM_ SG_ 2339766089 S2A_SUMDATA5_CUS_Reserve1_09 "客户预留数据";
CM_ SG_ 2339766089 S2A_SUMDATA5_CUS_Reserve2_09 "客户预留数据";
CM_ SG_ 2339766089 S2A_SUMDATA5_CUS_Reserve3_09 "客户预留数据";
CM_ SG_ 2339766089 S2A_SUMDATA5_CUS_Reserve4_09 "客户预留数据";
CM_ SG_ 2339766089 S2A_SUMDATA5_CUS_Reserve5_09 "客户预留数据";
CM_ SG_ 2339766089 S2A_SUMDATA5_CUS_Reserve6_09 "客户预留数据";
CM_ SG_ 2339766089 S2A_SUMDATA5_CUS_Reserve7_09 "客户预留数据";
CM_ SG_ 2339766089 S2A_SUMDATA5_CUS_Reserve8_09 "客户预留数据";
CM_ SG_ 2339766090 S2A_SUMDATA5_CUS_Reserve1_10 "客户预留数据";
CM_ SG_ 2339766090 S2A_SUMDATA5_CUS_Reserve2_10 "客户预留数据";
CM_ SG_ 2339766090 S2A_SUMDATA5_CUS_Reserve3_10 "客户预留数据";
CM_ SG_ 2339766090 S2A_SUMDATA5_CUS_Reserve4_10 "客户预留数据";
CM_ SG_ 2339766090 S2A_SUMDATA5_CUS_Reserve5_10 "客户预留数据";
CM_ SG_ 2339766090 S2A_SUMDATA5_CUS_Reserve6_10 "客户预留数据";
CM_ SG_ 2339766090 S2A_SUMDATA5_CUS_Reserve7_10 "客户预留数据";
CM_ SG_ 2339766090 S2A_SUMDATA5_CUS_Reserve8_10 "客户预留数据";
CM_ SG_ 2339766091 S2A_SUMDATA5_CUS_Reserve1_11 "客户预留数据";
CM_ SG_ 2339766091 S2A_SUMDATA5_CUS_Reserve2_11 "客户预留数据";
CM_ SG_ 2339766091 S2A_SUMDATA5_CUS_Reserve3_11 "客户预留数据";
CM_ SG_ 2339766091 S2A_SUMDATA5_CUS_Reserve4_11 "客户预留数据";
CM_ SG_ 2339766091 S2A_SUMDATA5_CUS_Reserve5_11 "客户预留数据";
CM_ SG_ 2339766091 S2A_SUMDATA5_CUS_Reserve6_11 "客户预留数据";
CM_ SG_ 2339766091 S2A_SUMDATA5_CUS_Reserve7_11 "客户预留数据";
CM_ SG_ 2339766091 S2A_SUMDATA5_CUS_Reserve8_11 "客户预留数据";
CM_ SG_ 2339766092 S2A_SUMDATA5_CUS_Reserve1_12 "客户预留数据";
CM_ SG_ 2339766092 S2A_SUMDATA5_CUS_Reserve2_12 "客户预留数据";
CM_ SG_ 2339766092 S2A_SUMDATA5_CUS_Reserve3_12 "客户预留数据";
CM_ SG_ 2339766092 S2A_SUMDATA5_CUS_Reserve4_12 "客户预留数据";
CM_ SG_ 2339766092 S2A_SUMDATA5_CUS_Reserve5_12 "客户预留数据";
CM_ SG_ 2339766092 S2A_SUMDATA5_CUS_Reserve6_12 "客户预留数据";
CM_ SG_ 2339766092 S2A_SUMDATA5_CUS_Reserve7_12 "客户预留数据";
CM_ SG_ 2339766092 S2A_SUMDATA5_CUS_Reserve8_12 "客户预留数据";
CM_ SG_ 2339766093 S2A_SUMDATA5_CUS_Reserve1_13 "客户预留数据";
CM_ SG_ 2339766093 S2A_SUMDATA5_CUS_Reserve2_13 "客户预留数据";
CM_ SG_ 2339766093 S2A_SUMDATA5_CUS_Reserve3_13 "客户预留数据";
CM_ SG_ 2339766093 S2A_SUMDATA5_CUS_Reserve4_13 "客户预留数据";
CM_ SG_ 2339766093 S2A_SUMDATA5_CUS_Reserve5_13 "客户预留数据";
CM_ SG_ 2339766093 S2A_SUMDATA5_CUS_Reserve6_13 "客户预留数据";
CM_ SG_ 2339766093 S2A_SUMDATA5_CUS_Reserve7_13 "客户预留数据";
CM_ SG_ 2339766093 S2A_SUMDATA5_CUS_Reserve8_13 "客户预留数据";
CM_ SG_ 2339766094 S2A_SUMDATA5_CUS_Reserve1_14 "客户预留数据";
CM_ SG_ 2339766094 S2A_SUMDATA5_CUS_Reserve2_14 "客户预留数据";
CM_ SG_ 2339766094 S2A_SUMDATA5_CUS_Reserve3_14 "客户预留数据";
CM_ SG_ 2339766094 S2A_SUMDATA5_CUS_Reserve4_14 "客户预留数据";
CM_ SG_ 2339766094 S2A_SUMDATA5_CUS_Reserve5_14 "客户预留数据";
CM_ SG_ 2339766094 S2A_SUMDATA5_CUS_Reserve6_14 "客户预留数据";
CM_ SG_ 2339766094 S2A_SUMDATA5_CUS_Reserve7_14 "客户预留数据";
CM_ SG_ 2339766094 S2A_SUMDATA5_CUS_Reserve8_14 "客户预留数据";
CM_ SG_ 2339766095 S2A_SUMDATA5_CUS_Reserve1_15 "客户预留数据";
CM_ SG_ 2339766095 S2A_SUMDATA5_CUS_Reserve2_15 "客户预留数据";
CM_ SG_ 2339766095 S2A_SUMDATA5_CUS_Reserve3_15 "客户预留数据";
CM_ SG_ 2339766095 S2A_SUMDATA5_CUS_Reserve4_15 "客户预留数据";
CM_ SG_ 2339766095 S2A_SUMDATA5_CUS_Reserve5_15 "客户预留数据";
CM_ SG_ 2339766095 S2A_SUMDATA5_CUS_Reserve6_15 "客户预留数据";
CM_ SG_ 2339766095 S2A_SUMDATA5_CUS_Reserve7_15 "客户预留数据";
CM_ SG_ 2339766095 S2A_SUMDATA5_CUS_Reserve8_15 "客户预留数据";
CM_ SG_ 2339766096 S2A_SUMDATA5_CUS_Reserve1_16 "客户预留数据";
CM_ SG_ 2339766096 S2A_SUMDATA5_CUS_Reserve2_16 "客户预留数据";
CM_ SG_ 2339766096 S2A_SUMDATA5_CUS_Reserve3_16 "客户预留数据";
CM_ SG_ 2339766096 S2A_SUMDATA5_CUS_Reserve4_16 "客户预留数据";
CM_ SG_ 2339766096 S2A_SUMDATA5_CUS_Reserve5_16 "客户预留数据";
CM_ SG_ 2339766096 S2A_SUMDATA5_CUS_Reserve6_16 "客户预留数据";
CM_ SG_ 2339766096 S2A_SUMDATA5_CUS_Reserve7_16 "客户预留数据";
CM_ SG_ 2339766096 S2A_SUMDATA5_CUS_Reserve8_16 "客户预留数据";
CM_ SG_ 2339766097 S2A_SUMDATA5_CUS_Reserve1_17 "客户预留数据";
CM_ SG_ 2339766097 S2A_SUMDATA5_CUS_Reserve2_17 "客户预留数据";
CM_ SG_ 2339766097 S2A_SUMDATA5_CUS_Reserve3_17 "客户预留数据";
CM_ SG_ 2339766097 S2A_SUMDATA5_CUS_Reserve4_17 "客户预留数据";
CM_ SG_ 2339766097 S2A_SUMDATA5_CUS_Reserve5_17 "客户预留数据";
CM_ SG_ 2339766097 S2A_SUMDATA5_CUS_Reserve6_17 "客户预留数据";
CM_ SG_ 2339766097 S2A_SUMDATA5_CUS_Reserve7_17 "客户预留数据";
CM_ SG_ 2339766097 S2A_SUMDATA5_CUS_Reserve8_17 "客户预留数据";
CM_ SG_ 2339766098 S2A_SUMDATA5_CUS_Reserve1_18 "客户预留数据";
CM_ SG_ 2339766098 S2A_SUMDATA5_CUS_Reserve2_18 "客户预留数据";
CM_ SG_ 2339766098 S2A_SUMDATA5_CUS_Reserve3_18 "客户预留数据";
CM_ SG_ 2339766098 S2A_SUMDATA5_CUS_Reserve4_18 "客户预留数据";
CM_ SG_ 2339766098 S2A_SUMDATA5_CUS_Reserve5_18 "客户预留数据";
CM_ SG_ 2339766098 S2A_SUMDATA5_CUS_Reserve6_18 "客户预留数据";
CM_ SG_ 2339766098 S2A_SUMDATA5_CUS_Reserve7_18 "客户预留数据";
CM_ SG_ 2339766098 S2A_SUMDATA5_CUS_Reserve8_18 "客户预留数据";
CM_ SG_ 2339766099 S2A_SUMDATA5_CUS_Reserve1_19 "客户预留数据";
CM_ SG_ 2339766099 S2A_SUMDATA5_CUS_Reserve2_19 "客户预留数据";
CM_ SG_ 2339766099 S2A_SUMDATA5_CUS_Reserve3_19 "客户预留数据";
CM_ SG_ 2339766099 S2A_SUMDATA5_CUS_Reserve4_19 "客户预留数据";
CM_ SG_ 2339766099 S2A_SUMDATA5_CUS_Reserve5_19 "客户预留数据";
CM_ SG_ 2339766099 S2A_SUMDATA5_CUS_Reserve6_19 "客户预留数据";
CM_ SG_ 2339766099 S2A_SUMDATA5_CUS_Reserve7_19 "客户预留数据";
CM_ SG_ 2339766099 S2A_SUMDATA5_CUS_Reserve8_19 "客户预留数据";
CM_ SG_ 2339766100 S2A_SUMDATA5_CUS_Reserve1_20 "客户预留数据";
CM_ SG_ 2339766100 S2A_SUMDATA5_CUS_Reserve2_20 "客户预留数据";
CM_ SG_ 2339766100 S2A_SUMDATA5_CUS_Reserve3_20 "客户预留数据";
CM_ SG_ 2339766100 S2A_SUMDATA5_CUS_Reserve4_20 "客户预留数据";
CM_ SG_ 2339766100 S2A_SUMDATA5_CUS_Reserve5_20 "客户预留数据";
CM_ SG_ 2339766100 S2A_SUMDATA5_CUS_Reserve6_20 "客户预留数据";
CM_ SG_ 2339766100 S2A_SUMDATA5_CUS_Reserve7_20 "客户预留数据";
CM_ SG_ 2339766100 S2A_SUMDATA5_CUS_Reserve8_20 "客户预留数据";
CM_ SG_ 2339766101 S2A_SUMDATA5_CUS_Reserve1_21 "客户预留数据";
CM_ SG_ 2339766101 S2A_SUMDATA5_CUS_Reserve2_21 "客户预留数据";
CM_ SG_ 2339766101 S2A_SUMDATA5_CUS_Reserve3_21 "客户预留数据";
CM_ SG_ 2339766101 S2A_SUMDATA5_CUS_Reserve4_21 "客户预留数据";
CM_ SG_ 2339766101 S2A_SUMDATA5_CUS_Reserve5_21 "客户预留数据";
CM_ SG_ 2339766101 S2A_SUMDATA5_CUS_Reserve6_21 "客户预留数据";
CM_ SG_ 2339766101 S2A_SUMDATA5_CUS_Reserve7_21 "客户预留数据";
CM_ SG_ 2339766101 S2A_SUMDATA5_CUS_Reserve8_21 "客户预留数据";
CM_ SG_ 2339766102 S2A_SUMDATA5_CUS_Reserve1_22 "客户预留数据";
CM_ SG_ 2339766102 S2A_SUMDATA5_CUS_Reserve2_22 "客户预留数据";
CM_ SG_ 2339766102 S2A_SUMDATA5_CUS_Reserve3_22 "客户预留数据";
CM_ SG_ 2339766102 S2A_SUMDATA5_CUS_Reserve4_22 "客户预留数据";
CM_ SG_ 2339766102 S2A_SUMDATA5_CUS_Reserve5_22 "客户预留数据";
CM_ SG_ 2339766102 S2A_SUMDATA5_CUS_Reserve6_22 "客户预留数据";
CM_ SG_ 2339766102 S2A_SUMDATA5_CUS_Reserve7_22 "客户预留数据";
CM_ SG_ 2339766102 S2A_SUMDATA5_CUS_Reserve8_22 "客户预留数据";
CM_ SG_ 2339766103 S2A_SUMDATA5_CUS_Reserve1_23 "客户预留数据";
CM_ SG_ 2339766103 S2A_SUMDATA5_CUS_Reserve2_23 "客户预留数据";
CM_ SG_ 2339766103 S2A_SUMDATA5_CUS_Reserve3_23 "客户预留数据";
CM_ SG_ 2339766103 S2A_SUMDATA5_CUS_Reserve4_23 "客户预留数据";
CM_ SG_ 2339766103 S2A_SUMDATA5_CUS_Reserve5_23 "客户预留数据";
CM_ SG_ 2339766103 S2A_SUMDATA5_CUS_Reserve6_23 "客户预留数据";
CM_ SG_ 2339766103 S2A_SUMDATA5_CUS_Reserve7_23 "客户预留数据";
CM_ SG_ 2339766103 S2A_SUMDATA5_CUS_Reserve8_23 "客户预留数据";
CM_ SG_ 2339766104 S2A_SUMDATA5_CUS_Reserve1_24 "客户预留数据";
CM_ SG_ 2339766104 S2A_SUMDATA5_CUS_Reserve2_24 "客户预留数据";
CM_ SG_ 2339766104 S2A_SUMDATA5_CUS_Reserve3_24 "客户预留数据";
CM_ SG_ 2339766104 S2A_SUMDATA5_CUS_Reserve4_24 "客户预留数据";
CM_ SG_ 2339766104 S2A_SUMDATA5_CUS_Reserve5_24 "客户预留数据";
CM_ SG_ 2339766104 S2A_SUMDATA5_CUS_Reserve6_24 "客户预留数据";
CM_ SG_ 2339766104 S2A_SUMDATA5_CUS_Reserve7_24 "客户预留数据";
CM_ SG_ 2339766104 S2A_SUMDATA5_CUS_Reserve8_24 "客户预留数据";
CM_ SG_ 2339766105 S2A_SUMDATA5_CUS_Reserve1_25 "客户预留数据";
CM_ SG_ 2339766105 S2A_SUMDATA5_CUS_Reserve2_25 "客户预留数据";
CM_ SG_ 2339766105 S2A_SUMDATA5_CUS_Reserve3_25 "客户预留数据";
CM_ SG_ 2339766105 S2A_SUMDATA5_CUS_Reserve4_25 "客户预留数据";
CM_ SG_ 2339766105 S2A_SUMDATA5_CUS_Reserve5_25 "客户预留数据";
CM_ SG_ 2339766105 S2A_SUMDATA5_CUS_Reserve6_25 "客户预留数据";
CM_ SG_ 2339766105 S2A_SUMDATA5_CUS_Reserve7_25 "客户预留数据";
CM_ SG_ 2339766105 S2A_SUMDATA5_CUS_Reserve8_25 "客户预留数据";
CM_ SG_ 2339766106 S2A_SUMDATA5_CUS_Reserve1_26 "客户预留数据";
CM_ SG_ 2339766106 S2A_SUMDATA5_CUS_Reserve2_26 "客户预留数据";
CM_ SG_ 2339766106 S2A_SUMDATA5_CUS_Reserve3_26 "客户预留数据";
CM_ SG_ 2339766106 S2A_SUMDATA5_CUS_Reserve4_26 "客户预留数据";
CM_ SG_ 2339766106 S2A_SUMDATA5_CUS_Reserve5_26 "客户预留数据";
CM_ SG_ 2339766106 S2A_SUMDATA5_CUS_Reserve6_26 "客户预留数据";
CM_ SG_ 2339766106 S2A_SUMDATA5_CUS_Reserve7_26 "客户预留数据";
CM_ SG_ 2339766106 S2A_SUMDATA5_CUS_Reserve8_26 "客户预留数据";
CM_ SG_ 2339766107 S2A_SUMDATA5_CUS_Reserve1_27 "客户预留数据";
CM_ SG_ 2339766107 S2A_SUMDATA5_CUS_Reserve2_27 "客户预留数据";
CM_ SG_ 2339766107 S2A_SUMDATA5_CUS_Reserve3_27 "客户预留数据";
CM_ SG_ 2339766107 S2A_SUMDATA5_CUS_Reserve4_27 "客户预留数据";
CM_ SG_ 2339766107 S2A_SUMDATA5_CUS_Reserve5_27 "客户预留数据";
CM_ SG_ 2339766107 S2A_SUMDATA5_CUS_Reserve6_27 "客户预留数据";
CM_ SG_ 2339766107 S2A_SUMDATA5_CUS_Reserve7_27 "客户预留数据";
CM_ SG_ 2339766107 S2A_SUMDATA5_CUS_Reserve8_27 "客户预留数据";
CM_ SG_ 2339766108 S2A_SUMDATA5_CUS_Reserve1_28 "客户预留数据";
CM_ SG_ 2339766108 S2A_SUMDATA5_CUS_Reserve2_28 "客户预留数据";
CM_ SG_ 2339766108 S2A_SUMDATA5_CUS_Reserve3_28 "客户预留数据";
CM_ SG_ 2339766108 S2A_SUMDATA5_CUS_Reserve4_28 "客户预留数据";
CM_ SG_ 2339766108 S2A_SUMDATA5_CUS_Reserve5_28 "客户预留数据";
CM_ SG_ 2339766108 S2A_SUMDATA5_CUS_Reserve6_28 "客户预留数据";
CM_ SG_ 2339766108 S2A_SUMDATA5_CUS_Reserve7_28 "客户预留数据";
CM_ SG_ 2339766108 S2A_SUMDATA5_CUS_Reserve8_28 "客户预留数据";
CM_ SG_ 2339766109 S2A_SUMDATA5_CUS_Reserve1_29 "客户预留数据";
CM_ SG_ 2339766109 S2A_SUMDATA5_CUS_Reserve2_29 "客户预留数据";
CM_ SG_ 2339766109 S2A_SUMDATA5_CUS_Reserve3_29 "客户预留数据";
CM_ SG_ 2339766109 S2A_SUMDATA5_CUS_Reserve4_29 "客户预留数据";
CM_ SG_ 2339766109 S2A_SUMDATA5_CUS_Reserve5_29 "客户预留数据";
CM_ SG_ 2339766109 S2A_SUMDATA5_CUS_Reserve6_29 "客户预留数据";
CM_ SG_ 2339766109 S2A_SUMDATA5_CUS_Reserve7_29 "客户预留数据";
CM_ SG_ 2339766109 S2A_SUMDATA5_CUS_Reserve8_29 "客户预留数据";
CM_ SG_ 2339766110 S2A_SUMDATA5_CUS_Reserve1_30 "客户预留数据";
CM_ SG_ 2339766110 S2A_SUMDATA5_CUS_Reserve2_30 "客户预留数据";
CM_ SG_ 2339766110 S2A_SUMDATA5_CUS_Reserve3_30 "客户预留数据";
CM_ SG_ 2339766110 S2A_SUMDATA5_CUS_Reserve4_30 "客户预留数据";
CM_ SG_ 2339766110 S2A_SUMDATA5_CUS_Reserve5_30 "客户预留数据";
CM_ SG_ 2339766110 S2A_SUMDATA5_CUS_Reserve6_30 "客户预留数据";
CM_ SG_ 2339766110 S2A_SUMDATA5_CUS_Reserve7_30 "客户预留数据";
CM_ SG_ 2339766110 S2A_SUMDATA5_CUS_Reserve8_30 "客户预留数据";
CM_ SG_ 2339766111 S2A_SUMDATA5_CUS_Reserve1_31 "客户预留数据";
CM_ SG_ 2339766111 S2A_SUMDATA5_CUS_Reserve2_31 "客户预留数据";
CM_ SG_ 2339766111 S2A_SUMDATA5_CUS_Reserve3_31 "客户预留数据";
CM_ SG_ 2339766111 S2A_SUMDATA5_CUS_Reserve4_31 "客户预留数据";
CM_ SG_ 2339766111 S2A_SUMDATA5_CUS_Reserve5_31 "客户预留数据";
CM_ SG_ 2339766111 S2A_SUMDATA5_CUS_Reserve6_31 "客户预留数据";
CM_ SG_ 2339766111 S2A_SUMDATA5_CUS_Reserve7_31 "客户预留数据";
CM_ SG_ 2339766111 S2A_SUMDATA5_CUS_Reserve8_31 "客户预留数据";
CM_ SG_ 2339766112 S2A_SUMDATA5_CUS_Reserve1_32 "客户预留数据";
CM_ SG_ 2339766112 S2A_SUMDATA5_CUS_Reserve2_32 "客户预留数据";
CM_ SG_ 2339766112 S2A_SUMDATA5_CUS_Reserve3_32 "客户预留数据";
CM_ SG_ 2339766112 S2A_SUMDATA5_CUS_Reserve4_32 "客户预留数据";
CM_ SG_ 2339766112 S2A_SUMDATA5_CUS_Reserve5_32 "客户预留数据";
CM_ SG_ 2339766112 S2A_SUMDATA5_CUS_Reserve6_32 "客户预留数据";
CM_ SG_ 2339766112 S2A_SUMDATA5_CUS_Reserve7_32 "客户预留数据";
CM_ SG_ 2339766112 S2A_SUMDATA5_CUS_Reserve8_32 "客户预留数据";
CM_ SG_ 2339766113 S2A_SUMDATA5_CUS_Reserve1_33 "客户预留数据";
CM_ SG_ 2339766113 S2A_SUMDATA5_CUS_Reserve2_33 "客户预留数据";
CM_ SG_ 2339766113 S2A_SUMDATA5_CUS_Reserve3_33 "客户预留数据";
CM_ SG_ 2339766113 S2A_SUMDATA5_CUS_Reserve4_33 "客户预留数据";
CM_ SG_ 2339766113 S2A_SUMDATA5_CUS_Reserve5_33 "客户预留数据";
CM_ SG_ 2339766113 S2A_SUMDATA5_CUS_Reserve6_33 "客户预留数据";
CM_ SG_ 2339766113 S2A_SUMDATA5_CUS_Reserve7_33 "客户预留数据";
CM_ SG_ 2339766113 S2A_SUMDATA5_CUS_Reserve8_33 "客户预留数据";
CM_ SG_ 2339766114 S2A_SUMDATA5_CUS_Reserve1_34 "客户预留数据";
CM_ SG_ 2339766114 S2A_SUMDATA5_CUS_Reserve2_34 "客户预留数据";
CM_ SG_ 2339766114 S2A_SUMDATA5_CUS_Reserve3_34 "客户预留数据";
CM_ SG_ 2339766114 S2A_SUMDATA5_CUS_Reserve4_34 "客户预留数据";
CM_ SG_ 2339766114 S2A_SUMDATA5_CUS_Reserve5_34 "客户预留数据";
CM_ SG_ 2339766114 S2A_SUMDATA5_CUS_Reserve6_34 "客户预留数据";
CM_ SG_ 2339766114 S2A_SUMDATA5_CUS_Reserve7_34 "客户预留数据";
CM_ SG_ 2339766114 S2A_SUMDATA5_CUS_Reserve8_34 "客户预留数据";
CM_ SG_ 2339766115 S2A_SUMDATA5_CUS_Reserve1_35 "客户预留数据";
CM_ SG_ 2339766115 S2A_SUMDATA5_CUS_Reserve2_35 "客户预留数据";
CM_ SG_ 2339766115 S2A_SUMDATA5_CUS_Reserve3_35 "客户预留数据";
CM_ SG_ 2339766115 S2A_SUMDATA5_CUS_Reserve4_35 "客户预留数据";
CM_ SG_ 2339766115 S2A_SUMDATA5_CUS_Reserve5_35 "客户预留数据";
CM_ SG_ 2339766115 S2A_SUMDATA5_CUS_Reserve6_35 "客户预留数据";
CM_ SG_ 2339766115 S2A_SUMDATA5_CUS_Reserve7_35 "客户预留数据";
CM_ SG_ 2339766115 S2A_SUMDATA5_CUS_Reserve8_35 "客户预留数据";
CM_ SG_ 2339766116 S2A_SUMDATA5_CUS_Reserve1_36 "客户预留数据";
CM_ SG_ 2339766116 S2A_SUMDATA5_CUS_Reserve2_36 "客户预留数据";
CM_ SG_ 2339766116 S2A_SUMDATA5_CUS_Reserve3_36 "客户预留数据";
CM_ SG_ 2339766116 S2A_SUMDATA5_CUS_Reserve4_36 "客户预留数据";
CM_ SG_ 2339766116 S2A_SUMDATA5_CUS_Reserve5_36 "客户预留数据";
CM_ SG_ 2339766116 S2A_SUMDATA5_CUS_Reserve6_36 "客户预留数据";
CM_ SG_ 2339766116 S2A_SUMDATA5_CUS_Reserve7_36 "客户预留数据";
CM_ SG_ 2339766116 S2A_SUMDATA5_CUS_Reserve8_36 "客户预留数据";
CM_ SG_ 2339766117 S2A_SUMDATA5_CUS_Reserve1_37 "客户预留数据";
CM_ SG_ 2339766117 S2A_SUMDATA5_CUS_Reserve2_37 "客户预留数据";
CM_ SG_ 2339766117 S2A_SUMDATA5_CUS_Reserve3_37 "客户预留数据";
CM_ SG_ 2339766117 S2A_SUMDATA5_CUS_Reserve4_37 "客户预留数据";
CM_ SG_ 2339766117 S2A_SUMDATA5_CUS_Reserve5_37 "客户预留数据";
CM_ SG_ 2339766117 S2A_SUMDATA5_CUS_Reserve6_37 "客户预留数据";
CM_ SG_ 2339766117 S2A_SUMDATA5_CUS_Reserve7_37 "客户预留数据";
CM_ SG_ 2339766117 S2A_SUMDATA5_CUS_Reserve8_37 "客户预留数据";
CM_ SG_ 2339766118 S2A_SUMDATA5_CUS_Reserve1_38 "客户预留数据";
CM_ SG_ 2339766118 S2A_SUMDATA5_CUS_Reserve2_38 "客户预留数据";
CM_ SG_ 2339766118 S2A_SUMDATA5_CUS_Reserve3_38 "客户预留数据";
CM_ SG_ 2339766118 S2A_SUMDATA5_CUS_Reserve4_38 "客户预留数据";
CM_ SG_ 2339766118 S2A_SUMDATA5_CUS_Reserve5_38 "客户预留数据";
CM_ SG_ 2339766118 S2A_SUMDATA5_CUS_Reserve6_38 "客户预留数据";
CM_ SG_ 2339766118 S2A_SUMDATA5_CUS_Reserve7_38 "客户预留数据";
CM_ SG_ 2339766118 S2A_SUMDATA5_CUS_Reserve8_38 "客户预留数据";
CM_ SG_ 2339766119 S2A_SUMDATA5_CUS_Reserve1_39 "客户预留数据";
CM_ SG_ 2339766119 S2A_SUMDATA5_CUS_Reserve2_39 "客户预留数据";
CM_ SG_ 2339766119 S2A_SUMDATA5_CUS_Reserve3_39 "客户预留数据";
CM_ SG_ 2339766119 S2A_SUMDATA5_CUS_Reserve4_39 "客户预留数据";
CM_ SG_ 2339766119 S2A_SUMDATA5_CUS_Reserve5_39 "客户预留数据";
CM_ SG_ 2339766119 S2A_SUMDATA5_CUS_Reserve6_39 "客户预留数据";
CM_ SG_ 2339766119 S2A_SUMDATA5_CUS_Reserve7_39 "客户预留数据";
CM_ SG_ 2339766119 S2A_SUMDATA5_CUS_Reserve8_39 "客户预留数据";
CM_ SG_ 2339766120 S2A_SUMDATA5_CUS_Reserve1_40 "客户预留数据";
CM_ SG_ 2339766120 S2A_SUMDATA5_CUS_Reserve2_40 "客户预留数据";
CM_ SG_ 2339766120 S2A_SUMDATA5_CUS_Reserve3_40 "客户预留数据";
CM_ SG_ 2339766120 S2A_SUMDATA5_CUS_Reserve4_40 "客户预留数据";
CM_ SG_ 2339766120 S2A_SUMDATA5_CUS_Reserve5_40 "客户预留数据";
CM_ SG_ 2339766120 S2A_SUMDATA5_CUS_Reserve6_40 "客户预留数据";
CM_ SG_ 2339766120 S2A_SUMDATA5_CUS_Reserve7_40 "客户预留数据";
CM_ SG_ 2339766120 S2A_SUMDATA5_CUS_Reserve8_40 "客户预留数据";
CM_ SG_ 2339766121 S2A_SUMDATA5_CUS_Reserve1_41 "客户预留数据";
CM_ SG_ 2339766121 S2A_SUMDATA5_CUS_Reserve2_41 "客户预留数据";
CM_ SG_ 2339766121 S2A_SUMDATA5_CUS_Reserve3_41 "客户预留数据";
CM_ SG_ 2339766121 S2A_SUMDATA5_CUS_Reserve4_41 "客户预留数据";
CM_ SG_ 2339766121 S2A_SUMDATA5_CUS_Reserve5_41 "客户预留数据";
CM_ SG_ 2339766121 S2A_SUMDATA5_CUS_Reserve6_41 "客户预留数据";
CM_ SG_ 2339766121 S2A_SUMDATA5_CUS_Reserve7_41 "客户预留数据";
CM_ SG_ 2339766121 S2A_SUMDATA5_CUS_Reserve8_41 "客户预留数据";
CM_ SG_ 2339766122 S2A_SUMDATA5_CUS_Reserve1_42 "客户预留数据";
CM_ SG_ 2339766122 S2A_SUMDATA5_CUS_Reserve2_42 "客户预留数据";
CM_ SG_ 2339766122 S2A_SUMDATA5_CUS_Reserve3_42 "客户预留数据";
CM_ SG_ 2339766122 S2A_SUMDATA5_CUS_Reserve4_42 "客户预留数据";
CM_ SG_ 2339766122 S2A_SUMDATA5_CUS_Reserve5_42 "客户预留数据";
CM_ SG_ 2339766122 S2A_SUMDATA5_CUS_Reserve6_42 "客户预留数据";
CM_ SG_ 2339766122 S2A_SUMDATA5_CUS_Reserve7_42 "客户预留数据";
CM_ SG_ 2339766122 S2A_SUMDATA5_CUS_Reserve8_42 "客户预留数据";
CM_ SG_ 2339766123 S2A_SUMDATA5_CUS_Reserve1_43 "客户预留数据";
CM_ SG_ 2339766123 S2A_SUMDATA5_CUS_Reserve2_43 "客户预留数据";
CM_ SG_ 2339766123 S2A_SUMDATA5_CUS_Reserve3_43 "客户预留数据";
CM_ SG_ 2339766123 S2A_SUMDATA5_CUS_Reserve4_43 "客户预留数据";
CM_ SG_ 2339766123 S2A_SUMDATA5_CUS_Reserve5_43 "客户预留数据";
CM_ SG_ 2339766123 S2A_SUMDATA5_CUS_Reserve6_43 "客户预留数据";
CM_ SG_ 2339766123 S2A_SUMDATA5_CUS_Reserve7_43 "客户预留数据";
CM_ SG_ 2339766123 S2A_SUMDATA5_CUS_Reserve8_43 "客户预留数据";
CM_ SG_ 2339766124 S2A_SUMDATA5_CUS_Reserve1_44 "客户预留数据";
CM_ SG_ 2339766124 S2A_SUMDATA5_CUS_Reserve2_44 "客户预留数据";
CM_ SG_ 2339766124 S2A_SUMDATA5_CUS_Reserve3_44 "客户预留数据";
CM_ SG_ 2339766124 S2A_SUMDATA5_CUS_Reserve4_44 "客户预留数据";
CM_ SG_ 2339766124 S2A_SUMDATA5_CUS_Reserve5_44 "客户预留数据";
CM_ SG_ 2339766124 S2A_SUMDATA5_CUS_Reserve6_44 "客户预留数据";
CM_ SG_ 2339766124 S2A_SUMDATA5_CUS_Reserve7_44 "客户预留数据";
CM_ SG_ 2339766124 S2A_SUMDATA5_CUS_Reserve8_44 "客户预留数据";
CM_ SG_ 2339766125 S2A_SUMDATA5_CUS_Reserve1_45 "客户预留数据";
CM_ SG_ 2339766125 S2A_SUMDATA5_CUS_Reserve2_45 "客户预留数据";
CM_ SG_ 2339766125 S2A_SUMDATA5_CUS_Reserve3_45 "客户预留数据";
CM_ SG_ 2339766125 S2A_SUMDATA5_CUS_Reserve4_45 "客户预留数据";
CM_ SG_ 2339766125 S2A_SUMDATA5_CUS_Reserve5_45 "客户预留数据";
CM_ SG_ 2339766125 S2A_SUMDATA5_CUS_Reserve6_45 "客户预留数据";
CM_ SG_ 2339766125 S2A_SUMDATA5_CUS_Reserve7_45 "客户预留数据";
CM_ SG_ 2339766125 S2A_SUMDATA5_CUS_Reserve8_45 "客户预留数据";
CM_ SG_ 2339766126 S2A_SUMDATA5_CUS_Reserve1_46 "客户预留数据";
CM_ SG_ 2339766126 S2A_SUMDATA5_CUS_Reserve2_46 "客户预留数据";
CM_ SG_ 2339766126 S2A_SUMDATA5_CUS_Reserve3_46 "客户预留数据";
CM_ SG_ 2339766126 S2A_SUMDATA5_CUS_Reserve4_46 "客户预留数据";
CM_ SG_ 2339766126 S2A_SUMDATA5_CUS_Reserve5_46 "客户预留数据";
CM_ SG_ 2339766126 S2A_SUMDATA5_CUS_Reserve6_46 "客户预留数据";
CM_ SG_ 2339766126 S2A_SUMDATA5_CUS_Reserve7_46 "客户预留数据";
CM_ SG_ 2339766126 S2A_SUMDATA5_CUS_Reserve8_46 "客户预留数据";
CM_ SG_ 2339766127 S2A_SUMDATA5_CUS_Reserve1_47 "客户预留数据";
CM_ SG_ 2339766127 S2A_SUMDATA5_CUS_Reserve2_47 "客户预留数据";
CM_ SG_ 2339766127 S2A_SUMDATA5_CUS_Reserve3_47 "客户预留数据";
CM_ SG_ 2339766127 S2A_SUMDATA5_CUS_Reserve4_47 "客户预留数据";
CM_ SG_ 2339766127 S2A_SUMDATA5_CUS_Reserve5_47 "客户预留数据";
CM_ SG_ 2339766127 S2A_SUMDATA5_CUS_Reserve6_47 "客户预留数据";
CM_ SG_ 2339766127 S2A_SUMDATA5_CUS_Reserve7_47 "客户预留数据";
CM_ SG_ 2339766127 S2A_SUMDATA5_CUS_Reserve8_47 "客户预留数据";
CM_ SG_ 2339766128 S2A_SUMDATA5_CUS_Reserve1_48 "客户预留数据";
CM_ SG_ 2339766128 S2A_SUMDATA5_CUS_Reserve2_48 "客户预留数据";
CM_ SG_ 2339766128 S2A_SUMDATA5_CUS_Reserve3_48 "客户预留数据";
CM_ SG_ 2339766128 S2A_SUMDATA5_CUS_Reserve4_48 "客户预留数据";
CM_ SG_ 2339766128 S2A_SUMDATA5_CUS_Reserve5_48 "客户预留数据";
CM_ SG_ 2339766128 S2A_SUMDATA5_CUS_Reserve6_48 "客户预留数据";
CM_ SG_ 2339766128 S2A_SUMDATA5_CUS_Reserve7_48 "客户预留数据";
CM_ SG_ 2339766128 S2A_SUMDATA5_CUS_Reserve8_48 "客户预留数据";
CM_ SG_ 2339766129 S2A_SUMDATA5_CUS_Reserve1_49 "客户预留数据";
CM_ SG_ 2339766129 S2A_SUMDATA5_CUS_Reserve2_49 "客户预留数据";
CM_ SG_ 2339766129 S2A_SUMDATA5_CUS_Reserve3_49 "客户预留数据";
CM_ SG_ 2339766129 S2A_SUMDATA5_CUS_Reserve4_49 "客户预留数据";
CM_ SG_ 2339766129 S2A_SUMDATA5_CUS_Reserve5_49 "客户预留数据";
CM_ SG_ 2339766129 S2A_SUMDATA5_CUS_Reserve6_49 "客户预留数据";
CM_ SG_ 2339766129 S2A_SUMDATA5_CUS_Reserve7_49 "客户预留数据";
CM_ SG_ 2339766129 S2A_SUMDATA5_CUS_Reserve8_49 "客户预留数据";
CM_ SG_ 2339766130 S2A_SUMDATA5_CUS_Reserve1_50 "客户预留数据";
CM_ SG_ 2339766130 S2A_SUMDATA5_CUS_Reserve2_50 "客户预留数据";
CM_ SG_ 2339766130 S2A_SUMDATA5_CUS_Reserve3_50 "客户预留数据";
CM_ SG_ 2339766130 S2A_SUMDATA5_CUS_Reserve4_50 "客户预留数据";
CM_ SG_ 2339766130 S2A_SUMDATA5_CUS_Reserve5_50 "客户预留数据";
CM_ SG_ 2339766130 S2A_SUMDATA5_CUS_Reserve6_50 "客户预留数据";
CM_ SG_ 2339766130 S2A_SUMDATA5_CUS_Reserve7_50 "客户预留数据";
CM_ SG_ 2339766130 S2A_SUMDATA5_CUS_Reserve8_50 "客户预留数据";
CM_ SG_ 2339766131 S2A_SUMDATA5_CUS_Reserve1_51 "客户预留数据";
CM_ SG_ 2339766131 S2A_SUMDATA5_CUS_Reserve2_51 "客户预留数据";
CM_ SG_ 2339766131 S2A_SUMDATA5_CUS_Reserve3_51 "客户预留数据";
CM_ SG_ 2339766131 S2A_SUMDATA5_CUS_Reserve4_51 "客户预留数据";
CM_ SG_ 2339766131 S2A_SUMDATA5_CUS_Reserve5_51 "客户预留数据";
CM_ SG_ 2339766131 S2A_SUMDATA5_CUS_Reserve6_51 "客户预留数据";
CM_ SG_ 2339766131 S2A_SUMDATA5_CUS_Reserve7_51 "客户预留数据";
CM_ SG_ 2339766131 S2A_SUMDATA5_CUS_Reserve8_51 "客户预留数据";
CM_ SG_ 2339766132 S2A_SUMDATA5_CUS_Reserve1_52 "客户预留数据";
CM_ SG_ 2339766132 S2A_SUMDATA5_CUS_Reserve2_52 "客户预留数据";
CM_ SG_ 2339766132 S2A_SUMDATA5_CUS_Reserve3_52 "客户预留数据";
CM_ SG_ 2339766132 S2A_SUMDATA5_CUS_Reserve4_52 "客户预留数据";
CM_ SG_ 2339766132 S2A_SUMDATA5_CUS_Reserve5_52 "客户预留数据";
CM_ SG_ 2339766132 S2A_SUMDATA5_CUS_Reserve6_52 "客户预留数据";
CM_ SG_ 2339766132 S2A_SUMDATA5_CUS_Reserve7_52 "客户预留数据";
CM_ SG_ 2339766132 S2A_SUMDATA5_CUS_Reserve8_52 "客户预留数据";
CM_ SG_ 2339766133 S2A_SUMDATA5_CUS_Reserve1_53 "客户预留数据";
CM_ SG_ 2339766133 S2A_SUMDATA5_CUS_Reserve2_53 "客户预留数据";
CM_ SG_ 2339766133 S2A_SUMDATA5_CUS_Reserve3_53 "客户预留数据";
CM_ SG_ 2339766133 S2A_SUMDATA5_CUS_Reserve4_53 "客户预留数据";
CM_ SG_ 2339766133 S2A_SUMDATA5_CUS_Reserve5_53 "客户预留数据";
CM_ SG_ 2339766133 S2A_SUMDATA5_CUS_Reserve6_53 "客户预留数据";
CM_ SG_ 2339766133 S2A_SUMDATA5_CUS_Reserve7_53 "客户预留数据";
CM_ SG_ 2339766133 S2A_SUMDATA5_CUS_Reserve8_53 "客户预留数据";
CM_ SG_ 2339766134 S2A_SUMDATA5_CUS_Reserve1_54 "客户预留数据";
CM_ SG_ 2339766134 S2A_SUMDATA5_CUS_Reserve2_54 "客户预留数据";
CM_ SG_ 2339766134 S2A_SUMDATA5_CUS_Reserve3_54 "客户预留数据";
CM_ SG_ 2339766134 S2A_SUMDATA5_CUS_Reserve4_54 "客户预留数据";
CM_ SG_ 2339766134 S2A_SUMDATA5_CUS_Reserve5_54 "客户预留数据";
CM_ SG_ 2339766134 S2A_SUMDATA5_CUS_Reserve6_54 "客户预留数据";
CM_ SG_ 2339766134 S2A_SUMDATA5_CUS_Reserve7_54 "客户预留数据";
CM_ SG_ 2339766134 S2A_SUMDATA5_CUS_Reserve8_54 "客户预留数据";
CM_ SG_ 2339766135 S2A_SUMDATA5_CUS_Reserve1_55 "客户预留数据";
CM_ SG_ 2339766135 S2A_SUMDATA5_CUS_Reserve2_55 "客户预留数据";
CM_ SG_ 2339766135 S2A_SUMDATA5_CUS_Reserve3_55 "客户预留数据";
CM_ SG_ 2339766135 S2A_SUMDATA5_CUS_Reserve4_55 "客户预留数据";
CM_ SG_ 2339766135 S2A_SUMDATA5_CUS_Reserve5_55 "客户预留数据";
CM_ SG_ 2339766135 S2A_SUMDATA5_CUS_Reserve6_55 "客户预留数据";
CM_ SG_ 2339766135 S2A_SUMDATA5_CUS_Reserve7_55 "客户预留数据";
CM_ SG_ 2339766135 S2A_SUMDATA5_CUS_Reserve8_55 "客户预留数据";
CM_ SG_ 2339766136 S2A_SUMDATA5_CUS_Reserve1_56 "客户预留数据";
CM_ SG_ 2339766136 S2A_SUMDATA5_CUS_Reserve2_56 "客户预留数据";
CM_ SG_ 2339766136 S2A_SUMDATA5_CUS_Reserve3_56 "客户预留数据";
CM_ SG_ 2339766136 S2A_SUMDATA5_CUS_Reserve4_56 "客户预留数据";
CM_ SG_ 2339766136 S2A_SUMDATA5_CUS_Reserve5_56 "客户预留数据";
CM_ SG_ 2339766136 S2A_SUMDATA5_CUS_Reserve6_56 "客户预留数据";
CM_ SG_ 2339766136 S2A_SUMDATA5_CUS_Reserve7_56 "客户预留数据";
CM_ SG_ 2339766136 S2A_SUMDATA5_CUS_Reserve8_56 "客户预留数据";
CM_ SG_ 2339766137 S2A_SUMDATA5_CUS_Reserve1_57 "客户预留数据";
CM_ SG_ 2339766137 S2A_SUMDATA5_CUS_Reserve2_57 "客户预留数据";
CM_ SG_ 2339766137 S2A_SUMDATA5_CUS_Reserve3_57 "客户预留数据";
CM_ SG_ 2339766137 S2A_SUMDATA5_CUS_Reserve4_57 "客户预留数据";
CM_ SG_ 2339766137 S2A_SUMDATA5_CUS_Reserve5_57 "客户预留数据";
CM_ SG_ 2339766137 S2A_SUMDATA5_CUS_Reserve6_57 "客户预留数据";
CM_ SG_ 2339766137 S2A_SUMDATA5_CUS_Reserve7_57 "客户预留数据";
CM_ SG_ 2339766137 S2A_SUMDATA5_CUS_Reserve8_57 "客户预留数据";
CM_ SG_ 2339766138 S2A_SUMDATA5_CUS_Reserve1_58 "客户预留数据";
CM_ SG_ 2339766138 S2A_SUMDATA5_CUS_Reserve2_58 "客户预留数据";
CM_ SG_ 2339766138 S2A_SUMDATA5_CUS_Reserve3_58 "客户预留数据";
CM_ SG_ 2339766138 S2A_SUMDATA5_CUS_Reserve4_58 "客户预留数据";
CM_ SG_ 2339766138 S2A_SUMDATA5_CUS_Reserve5_58 "客户预留数据";
CM_ SG_ 2339766138 S2A_SUMDATA5_CUS_Reserve6_58 "客户预留数据";
CM_ SG_ 2339766138 S2A_SUMDATA5_CUS_Reserve7_58 "客户预留数据";
CM_ SG_ 2339766138 S2A_SUMDATA5_CUS_Reserve8_58 "客户预留数据";
CM_ SG_ 2339766139 S2A_SUMDATA5_CUS_Reserve1_59 "客户预留数据";
CM_ SG_ 2339766139 S2A_SUMDATA5_CUS_Reserve2_59 "客户预留数据";
CM_ SG_ 2339766139 S2A_SUMDATA5_CUS_Reserve3_59 "客户预留数据";
CM_ SG_ 2339766139 S2A_SUMDATA5_CUS_Reserve4_59 "客户预留数据";
CM_ SG_ 2339766139 S2A_SUMDATA5_CUS_Reserve5_59 "客户预留数据";
CM_ SG_ 2339766139 S2A_SUMDATA5_CUS_Reserve6_59 "客户预留数据";
CM_ SG_ 2339766139 S2A_SUMDATA5_CUS_Reserve7_59 "客户预留数据";
CM_ SG_ 2339766139 S2A_SUMDATA5_CUS_Reserve8_59 "客户预留数据";
CM_ SG_ 2339766140 S2A_SUMDATA5_CUS_Reserve1_60 "客户预留数据";
CM_ SG_ 2339766140 S2A_SUMDATA5_CUS_Reserve2_60 "客户预留数据";
CM_ SG_ 2339766140 S2A_SUMDATA5_CUS_Reserve3_60 "客户预留数据";
CM_ SG_ 2339766140 S2A_SUMDATA5_CUS_Reserve4_60 "客户预留数据";
CM_ SG_ 2339766140 S2A_SUMDATA5_CUS_Reserve5_60 "客户预留数据";
CM_ SG_ 2339766140 S2A_SUMDATA5_CUS_Reserve6_60 "客户预留数据";
CM_ SG_ 2339766140 S2A_SUMDATA5_CUS_Reserve7_60 "客户预留数据";
CM_ SG_ 2339766140 S2A_SUMDATA5_CUS_Reserve8_60 "客户预留数据";
CM_ SG_ 2339766141 S2A_SUMDATA5_CUS_Reserve1_61 "客户预留数据";
CM_ SG_ 2339766141 S2A_SUMDATA5_CUS_Reserve2_61 "客户预留数据";
CM_ SG_ 2339766141 S2A_SUMDATA5_CUS_Reserve3_61 "客户预留数据";
CM_ SG_ 2339766141 S2A_SUMDATA5_CUS_Reserve4_61 "客户预留数据";
CM_ SG_ 2339766141 S2A_SUMDATA5_CUS_Reserve5_61 "客户预留数据";
CM_ SG_ 2339766141 S2A_SUMDATA5_CUS_Reserve6_61 "客户预留数据";
CM_ SG_ 2339766141 S2A_SUMDATA5_CUS_Reserve7_61 "客户预留数据";
CM_ SG_ 2339766141 S2A_SUMDATA5_CUS_Reserve8_61 "客户预留数据";
CM_ SG_ 2339766142 S2A_SUMDATA5_CUS_Reserve1_62 "客户预留数据";
CM_ SG_ 2339766142 S2A_SUMDATA5_CUS_Reserve2_62 "客户预留数据";
CM_ SG_ 2339766142 S2A_SUMDATA5_CUS_Reserve3_62 "客户预留数据";
CM_ SG_ 2339766142 S2A_SUMDATA5_CUS_Reserve4_62 "客户预留数据";
CM_ SG_ 2339766142 S2A_SUMDATA5_CUS_Reserve5_62 "客户预留数据";
CM_ SG_ 2339766142 S2A_SUMDATA5_CUS_Reserve6_62 "客户预留数据";
CM_ SG_ 2339766142 S2A_SUMDATA5_CUS_Reserve7_62 "客户预留数据";
CM_ SG_ 2339766142 S2A_SUMDATA5_CUS_Reserve8_62 "客户预留数据";
CM_ SG_ 2339766143 S2A_SUMDATA5_CUS_Reserve1_63 "客户预留数据";
CM_ SG_ 2339766143 S2A_SUMDATA5_CUS_Reserve2_63 "客户预留数据";
CM_ SG_ 2339766143 S2A_SUMDATA5_CUS_Reserve3_63 "客户预留数据";
CM_ SG_ 2339766143 S2A_SUMDATA5_CUS_Reserve4_63 "客户预留数据";
CM_ SG_ 2339766143 S2A_SUMDATA5_CUS_Reserve5_63 "客户预留数据";
CM_ SG_ 2339766143 S2A_SUMDATA5_CUS_Reserve6_63 "客户预留数据";
CM_ SG_ 2339766143 S2A_SUMDATA5_CUS_Reserve7_63 "客户预留数据";
CM_ SG_ 2339766143 S2A_SUMDATA5_CUS_Reserve8_63 "客户预留数据";
CM_ SG_ 2148749633 CellHeatMode_Status "BMS自加热的状态";
CM_ SG_ 2148749633 CellHeatMode_PermitStatus "SBMU反馈自加热允许状态";
CM_ SG_ 2148749634 CellHeatMode_Status "BMS自加热的状态";
CM_ SG_ 2148749634 CellHeatMode_PermitStatus "SBMU反馈自加热允许状态";
CM_ SG_ 2148749635 CellHeatMode_Status "BMS自加热的状态";
CM_ SG_ 2148749635 CellHeatMode_PermitStatus "SBMU反馈自加热允许状态";
CM_ SG_ 2148749636 CellHeatMode_Status "BMS自加热的状态";
CM_ SG_ 2148749636 CellHeatMode_PermitStatus "SBMU反馈自加热允许状态";
CM_ SG_ 2148749637 CellHeatMode_Status "BMS自加热的状态";
CM_ SG_ 2148749637 CellHeatMode_PermitStatus "SBMU反馈自加热允许状态";
CM_ SG_ 2148749638 CellHeatMode_Status "BMS自加热的状态";
CM_ SG_ 2148749638 CellHeatMode_PermitStatus "SBMU反馈自加热允许状态";
CM_ SG_ 2148749639 CellHeatMode_Status "BMS自加热的状态";
CM_ SG_ 2148749639 CellHeatMode_PermitStatus "SBMU反馈自加热允许状态";
CM_ SG_ 2148749640 CellHeatMode_Status "BMS自加热的状态";
CM_ SG_ 2148749640 CellHeatMode_PermitStatus "SBMU反馈自加热允许状态";
CM_ SG_ 2148749641 CellHeatMode_Status "BMS自加热的状态";
CM_ SG_ 2148749641 CellHeatMode_PermitStatus "SBMU反馈自加热允许状态";
CM_ SG_ 2148749642 CellHeatMode_Status "BMS自加热的状态";
CM_ SG_ 2148749642 CellHeatMode_PermitStatus "SBMU反馈自加热允许状态";
CM_ SG_ 2148749643 CellHeatMode_Status "BMS自加热的状态";
CM_ SG_ 2148749643 CellHeatMode_PermitStatus "SBMU反馈自加热允许状态";
CM_ SG_ 2148749644 CellHeatMode_Status "BMS自加热的状态";
CM_ SG_ 2148749644 CellHeatMode_PermitStatus "SBMU反馈自加热允许状态";
CM_ SG_ 2148749645 CellHeatMode_Status "BMS自加热的状态";
CM_ SG_ 2148749645 CellHeatMode_PermitStatus "SBMU反馈自加热允许状态";
CM_ SG_ 2148749646 CellHeatMode_Status "BMS自加热的状态";
CM_ SG_ 2148749646 CellHeatMode_PermitStatus "SBMU反馈自加热允许状态";
CM_ SG_ 2148749647 CellHeatMode_Status "BMS自加热的状态";
CM_ SG_ 2148749647 CellHeatMode_PermitStatus "SBMU反馈自加热允许状态";
CM_ SG_ 2148749648 CellHeatMode_Status "BMS自加热的状态";
CM_ SG_ 2148749648 CellHeatMode_PermitStatus "SBMU反馈自加热允许状态";
CM_ SG_ 2148749649 CellHeatMode_Status "BMS自加热的状态";
CM_ SG_ 2148749649 CellHeatMode_PermitStatus "SBMU反馈自加热允许状态";
CM_ SG_ 2148749650 CellHeatMode_Status "BMS自加热的状态";
CM_ SG_ 2148749650 CellHeatMode_PermitStatus "SBMU反馈自加热允许状态";
CM_ SG_ 2148749651 CellHeatMode_Status "BMS自加热的状态";
CM_ SG_ 2148749651 CellHeatMode_PermitStatus "SBMU反馈自加热允许状态";
CM_ SG_ 2148749652 CellHeatMode_Status "BMS自加热的状态";
CM_ SG_ 2148749652 CellHeatMode_PermitStatus "SBMU反馈自加热允许状态";
CM_ SG_ 2148749653 CellHeatMode_Status "BMS自加热的状态";
CM_ SG_ 2148749653 CellHeatMode_PermitStatus "SBMU反馈自加热允许状态";
CM_ SG_ 2148749654 CellHeatMode_Status "BMS自加热的状态";
CM_ SG_ 2148749654 CellHeatMode_PermitStatus "SBMU反馈自加热允许状态";
CM_ SG_ 2148749655 CellHeatMode_Status "BMS自加热的状态";
CM_ SG_ 2148749655 CellHeatMode_PermitStatus "SBMU反馈自加热允许状态";
CM_ SG_ 2148749656 CellHeatMode_Status "BMS自加热的状态";
CM_ SG_ 2148749656 CellHeatMode_PermitStatus "SBMU反馈自加热允许状态";
CM_ SG_ 2148749657 CellHeatMode_Status "BMS自加热的状态";
CM_ SG_ 2148749657 CellHeatMode_PermitStatus "SBMU反馈自加热允许状态";
CM_ SG_ 2148749658 CellHeatMode_Status "BMS自加热的状态";
CM_ SG_ 2148749658 CellHeatMode_PermitStatus "SBMU反馈自加热允许状态";
CM_ SG_ 2148749659 CellHeatMode_Status "BMS自加热的状态";
CM_ SG_ 2148749659 CellHeatMode_PermitStatus "SBMU反馈自加热允许状态";
CM_ SG_ 2148749660 CellHeatMode_Status "BMS自加热的状态";
CM_ SG_ 2148749660 CellHeatMode_PermitStatus "SBMU反馈自加热允许状态";
CM_ SG_ 2148749661 CellHeatMode_Status "BMS自加热的状态";
CM_ SG_ 2148749661 CellHeatMode_PermitStatus "SBMU反馈自加热允许状态";
CM_ SG_ 2148749662 CellHeatMode_Status "BMS自加热的状态";
CM_ SG_ 2148749662 CellHeatMode_PermitStatus "SBMU反馈自加热允许状态";
CM_ SG_ 2148749663 CellHeatMode_Status "BMS自加热的状态";
CM_ SG_ 2148749663 CellHeatMode_PermitStatus "SBMU反馈自加热允许状态";
CM_ SG_ 2148749664 CellHeatMode_Status "BMS自加热的状态";
CM_ SG_ 2148749664 CellHeatMode_PermitStatus "SBMU反馈自加热允许状态";
CM_ SG_ 2148749665 CellHeatMode_Status "BMS自加热的状态";
CM_ SG_ 2148749665 CellHeatMode_PermitStatus "SBMU反馈自加热允许状态";
CM_ SG_ 2148749666 CellHeatMode_Status "BMS自加热的状态";
CM_ SG_ 2148749666 CellHeatMode_PermitStatus "SBMU反馈自加热允许状态";
CM_ SG_ 2148749667 CellHeatMode_Status "BMS自加热的状态";
CM_ SG_ 2148749667 CellHeatMode_PermitStatus "SBMU反馈自加热允许状态";
CM_ SG_ 2148749668 CellHeatMode_Status "BMS自加热的状态";
CM_ SG_ 2148749668 CellHeatMode_PermitStatus "SBMU反馈自加热允许状态";
CM_ SG_ 2148749669 CellHeatMode_Status "BMS自加热的状态";
CM_ SG_ 2148749669 CellHeatMode_PermitStatus "SBMU反馈自加热允许状态";
CM_ SG_ 2148749670 CellHeatMode_Status "BMS自加热的状态";
CM_ SG_ 2148749670 CellHeatMode_PermitStatus "SBMU反馈自加热允许状态";
VAL_ 2148749633 CellHeatMode_Status 0 "非自加热模式" 1 "自加热模式" ;
VAL_ 2148749633 CellHeatMode_PermitStatus 0 "允许自加热" 1 "禁止自加热" ;
VAL_ 2148749634 CellHeatMode_Status 0 "非自加热模式" 1 "自加热模式" ;
VAL_ 2148749634 CellHeatMode_PermitStatus 0 "允许自加热" 1 "禁止自加热" ;
VAL_ 2148749635 CellHeatMode_Status 0 "非自加热模式" 1 "自加热模式" ;
VAL_ 2148749635 CellHeatMode_PermitStatus 0 "允许自加热" 1 "禁止自加热" ;
VAL_ 2148749636 CellHeatMode_Status 0 "非自加热模式" 1 "自加热模式" ;
VAL_ 2148749636 CellHeatMode_PermitStatus 0 "允许自加热" 1 "禁止自加热" ;
VAL_ 2148749637 CellHeatMode_Status 0 "非自加热模式" 1 "自加热模式" ;
VAL_ 2148749637 CellHeatMode_PermitStatus 0 "允许自加热" 1 "禁止自加热" ;
VAL_ 2148749638 CellHeatMode_Status 0 "非自加热模式" 1 "自加热模式" ;
VAL_ 2148749638 CellHeatMode_PermitStatus 0 "允许自加热" 1 "禁止自加热" ;
VAL_ 2148749639 CellHeatMode_Status 0 "非自加热模式" 1 "自加热模式" ;
VAL_ 2148749639 CellHeatMode_PermitStatus 0 "允许自加热" 1 "禁止自加热" ;
VAL_ 2148749640 CellHeatMode_Status 0 "非自加热模式" 1 "自加热模式" ;
VAL_ 2148749640 CellHeatMode_PermitStatus 0 "允许自加热" 1 "禁止自加热" ;
VAL_ 2148749641 CellHeatMode_Status 0 "非自加热模式" 1 "自加热模式" ;
VAL_ 2148749641 CellHeatMode_PermitStatus 0 "允许自加热" 1 "禁止自加热" ;
VAL_ 2148749642 CellHeatMode_Status 0 "非自加热模式" 1 "自加热模式" ;
VAL_ 2148749642 CellHeatMode_PermitStatus 0 "允许自加热" 1 "禁止自加热" ;
VAL_ 2148749643 CellHeatMode_Status 0 "非自加热模式" 1 "自加热模式" ;
VAL_ 2148749643 CellHeatMode_PermitStatus 0 "允许自加热" 1 "禁止自加热" ;
VAL_ 2148749644 CellHeatMode_Status 0 "非自加热模式" 1 "自加热模式" ;
VAL_ 2148749644 CellHeatMode_PermitStatus 0 "允许自加热" 1 "禁止自加热" ;
VAL_ 2148749645 CellHeatMode_Status 0 "非自加热模式" 1 "自加热模式" ;
VAL_ 2148749645 CellHeatMode_PermitStatus 0 "允许自加热" 1 "禁止自加热" ;
VAL_ 2148749646 CellHeatMode_Status 0 "非自加热模式" 1 "自加热模式" ;
VAL_ 2148749646 CellHeatMode_PermitStatus 0 "允许自加热" 1 "禁止自加热" ;
VAL_ 2148749647 CellHeatMode_Status 0 "非自加热模式" 1 "自加热模式" ;
VAL_ 2148749647 CellHeatMode_PermitStatus 0 "允许自加热" 1 "禁止自加热" ;
VAL_ 2148749648 CellHeatMode_Status 0 "非自加热模式" 1 "自加热模式" ;
VAL_ 2148749648 CellHeatMode_PermitStatus 0 "允许自加热" 1 "禁止自加热" ;
VAL_ 2148749649 CellHeatMode_Status 0 "非自加热模式" 1 "自加热模式" ;
VAL_ 2148749649 CellHeatMode_PermitStatus 0 "允许自加热" 1 "禁止自加热" ;
VAL_ 2148749650 CellHeatMode_Status 0 "非自加热模式" 1 "自加热模式" ;
VAL_ 2148749650 CellHeatMode_PermitStatus 0 "允许自加热" 1 "禁止自加热" ;
VAL_ 2148749651 CellHeatMode_Status 0 "非自加热模式" 1 "自加热模式" ;
VAL_ 2148749651 CellHeatMode_PermitStatus 0 "允许自加热" 1 "禁止自加热" ;
VAL_ 2148749652 CellHeatMode_Status 0 "非自加热模式" 1 "自加热模式" ;
VAL_ 2148749652 CellHeatMode_PermitStatus 0 "允许自加热" 1 "禁止自加热" ;
VAL_ 2148749653 CellHeatMode_Status 0 "非自加热模式" 1 "自加热模式" ;
VAL_ 2148749653 CellHeatMode_PermitStatus 0 "允许自加热" 1 "禁止自加热" ;
VAL_ 2148749654 CellHeatMode_Status 0 "非自加热模式" 1 "自加热模式" ;
VAL_ 2148749654 CellHeatMode_PermitStatus 0 "允许自加热" 1 "禁止自加热" ;
VAL_ 2148749655 CellHeatMode_Status 0 "非自加热模式" 1 "自加热模式" ;
VAL_ 2148749655 CellHeatMode_PermitStatus 0 "允许自加热" 1 "禁止自加热" ;
VAL_ 2148749656 CellHeatMode_Status 0 "非自加热模式" 1 "自加热模式" ;
VAL_ 2148749656 CellHeatMode_PermitStatus 0 "允许自加热" 1 "禁止自加热" ;
VAL_ 2148749657 CellHeatMode_Status 0 "非自加热模式" 1 "自加热模式" ;
VAL_ 2148749657 CellHeatMode_PermitStatus 0 "允许自加热" 1 "禁止自加热" ;
VAL_ 2148749658 CellHeatMode_Status 0 "非自加热模式" 1 "自加热模式" ;
VAL_ 2148749658 CellHeatMode_PermitStatus 0 "允许自加热" 1 "禁止自加热" ;
VAL_ 2148749659 CellHeatMode_Status 0 "非自加热模式" 1 "自加热模式" ;
VAL_ 2148749659 CellHeatMode_PermitStatus 0 "允许自加热" 1 "禁止自加热" ;
VAL_ 2148749660 CellHeatMode_Status 0 "非自加热模式" 1 "自加热模式" ;
VAL_ 2148749660 CellHeatMode_PermitStatus 0 "允许自加热" 1 "禁止自加热" ;
VAL_ 2148749661 CellHeatMode_Status 0 "非自加热模式" 1 "自加热模式" ;
VAL_ 2148749661 CellHeatMode_PermitStatus 0 "允许自加热" 1 "禁止自加热" ;
VAL_ 2148749662 CellHeatMode_Status 0 "非自加热模式" 1 "自加热模式" ;
VAL_ 2148749662 CellHeatMode_PermitStatus 0 "允许自加热" 1 "禁止自加热" ;
VAL_ 2148749663 CellHeatMode_Status 0 "非自加热模式" 1 "自加热模式" ;
VAL_ 2148749663 CellHeatMode_PermitStatus 0 "允许自加热" 1 "禁止自加热" ;
VAL_ 2148749664 CellHeatMode_Status 0 "非自加热模式" 1 "自加热模式" ;
VAL_ 2148749664 CellHeatMode_PermitStatus 0 "允许自加热" 1 "禁止自加热" ;
VAL_ 2148749665 CellHeatMode_Status 0 "非自加热模式" 1 "自加热模式" ;
VAL_ 2148749665 CellHeatMode_PermitStatus 0 "允许自加热" 1 "禁止自加热" ;
VAL_ 2148749666 CellHeatMode_Status 0 "非自加热模式" 1 "自加热模式" ;
VAL_ 2148749666 CellHeatMode_PermitStatus 0 "允许自加热" 1 "禁止自加热" ;
VAL_ 2148749667 CellHeatMode_Status 0 "非自加热模式" 1 "自加热模式" ;
VAL_ 2148749667 CellHeatMode_PermitStatus 0 "允许自加热" 1 "禁止自加热" ;
VAL_ 2148749668 CellHeatMode_Status 0 "非自加热模式" 1 "自加热模式" ;
VAL_ 2148749668 CellHeatMode_PermitStatus 0 "允许自加热" 1 "禁止自加热" ;
VAL_ 2148749669 CellHeatMode_Status 0 "非自加热模式" 1 "自加热模式" ;
VAL_ 2148749669 CellHeatMode_PermitStatus 0 "允许自加热" 1 "禁止自加热" ;
VAL_ 2148749670 CellHeatMode_Status 0 "非自加热模式" 1 "自加热模式" ;
VAL_ 2148749670 CellHeatMode_PermitStatus 0 "允许自加热" 1 "禁止自加热" ;
VERSION ""

NS_ :

BS_:

BU_: MBMU PC SBMU IMM ETH DCDC LEMS

BO_ 2148749671 S2L_SUMDATA1__39: 8 SBMU
 SG_ CellHeatMode_Status : 4|1@1+ (1,0) [0|1] ""  PC,MBMU
 SG_ CellHeatMode_PermitStatus : 22|1@1+ (1,0) [0|1] ""  PC,MBMU

BO_ 2148749672 S2L_SUMDATA1__40: 8 SBMU
 SG_ CellHeatMode_Status : 4|1@1+ (1,0) [0|1] ""  PC,MBMU
 SG_ CellHeatMode_PermitStatus : 22|1@1+ (1,0) [0|1] ""  PC,MBMU

BO_ 2148749673 S2L_SUMDATA1__41: 8 SBMU
 SG_ CellHeatMode_Status : 4|1@1+ (1,0) [0|1] ""  PC,MBMU
 SG_ CellHeatMode_PermitStatus : 22|1@1+ (1,0) [0|1] ""  PC,MBMU

BO_ 2148749674 S2L_SUMDATA1__42: 8 SBMU
 SG_ CellHeatMode_Status : 4|1@1+ (1,0) [0|1] ""  PC,MBMU
 SG_ CellHeatMode_PermitStatus : 22|1@1+ (1,0) [0|1] ""  PC,MBMU

BO_ 2148749675 S2L_SUMDATA1__43: 8 SBMU
 SG_ CellHeatMode_Status : 4|1@1+ (1,0) [0|1] ""  PC,MBMU
 SG_ CellHeatMode_PermitStatus : 22|1@1+ (1,0) [0|1] ""  PC,MBMU

BO_ 2148749676 S2L_SUMDATA1__44: 8 SBMU
 SG_ CellHeatMode_Status : 4|1@1+ (1,0) [0|1] ""  PC,MBMU
 SG_ CellHeatMode_PermitStatus : 22|1@1+ (1,0) [0|1] ""  PC,MBMU

BO_ 2148749677 S2L_SUMDATA1__45: 8 SBMU
 SG_ CellHeatMode_Status : 4|1@1+ (1,0) [0|1] ""  PC,MBMU
 SG_ CellHeatMode_PermitStatus : 22|1@1+ (1,0) [0|1] ""  PC,MBMU

BO_ 2148749678 S2L_SUMDATA1__46: 8 SBMU
 SG_ CellHeatMode_Status : 4|1@1+ (1,0) [0|1] ""  PC,MBMU
 SG_ CellHeatMode_PermitStatus : 22|1@1+ (1,0) [0|1] ""  PC,MBMU

BO_ 2148749679 S2L_SUMDATA1__47: 8 SBMU
 SG_ CellHeatMode_Status : 4|1@1+ (1,0) [0|1] ""  PC,MBMU
 SG_ CellHeatMode_PermitStatus : 22|1@1+ (1,0) [0|1] ""  PC,MBMU

BO_ 2148749680 S2L_SUMDATA1__48: 8 SBMU
 SG_ CellHeatMode_Status : 4|1@1+ (1,0) [0|1] ""  PC,MBMU
 SG_ CellHeatMode_PermitStatus : 22|1@1+ (1,0) [0|1] ""  PC,MBMU

BO_ 2148749681 S2L_SUMDATA1__49: 8 SBMU
 SG_ CellHeatMode_Status : 4|1@1+ (1,0) [0|1] ""  PC,MBMU
 SG_ CellHeatMode_PermitStatus : 22|1@1+ (1,0) [0|1] ""  PC,MBMU

BO_ 2148749682 S2L_SUMDATA1__50: 8 SBMU
 SG_ CellHeatMode_Status : 4|1@1+ (1,0) [0|1] ""  PC,MBMU
 SG_ CellHeatMode_PermitStatus : 22|1@1+ (1,0) [0|1] ""  PC,MBMU

BO_ 2148749683 S2L_SUMDATA1__51: 8 SBMU
 SG_ CellHeatMode_Status : 4|1@1+ (1,0) [0|1] ""  PC,MBMU
 SG_ CellHeatMode_PermitStatus : 22|1@1+ (1,0) [0|1] ""  PC,MBMU

BO_ 2148749684 S2L_SUMDATA1__52: 8 SBMU
 SG_ CellHeatMode_Status : 4|1@1+ (1,0) [0|1] ""  PC,MBMU
 SG_ CellHeatMode_PermitStatus : 22|1@1+ (1,0) [0|1] ""  PC,MBMU

BO_ 2148749685 S2L_SUMDATA1__53: 8 SBMU
 SG_ CellHeatMode_Status : 4|1@1+ (1,0) [0|1] ""  PC,MBMU
 SG_ CellHeatMode_PermitStatus : 22|1@1+ (1,0) [0|1] ""  PC,MBMU

BO_ 2148749686 S2L_SUMDATA1__54: 8 SBMU
 SG_ CellHeatMode_Status : 4|1@1+ (1,0) [0|1] ""  PC,MBMU
 SG_ CellHeatMode_PermitStatus : 22|1@1+ (1,0) [0|1] ""  PC,MBMU

BO_ 2148749687 S2L_SUMDATA1__55: 8 SBMU
 SG_ CellHeatMode_Status : 4|1@1+ (1,0) [0|1] ""  PC,MBMU
 SG_ CellHeatMode_PermitStatus : 22|1@1+ (1,0) [0|1] ""  PC,MBMU

BO_ 2148749688 S2L_SUMDATA1__56: 8 SBMU
 SG_ CellHeatMode_Status : 4|1@1+ (1,0) [0|1] ""  PC,MBMU
 SG_ CellHeatMode_PermitStatus : 22|1@1+ (1,0) [0|1] ""  PC,MBMU

BO_ 2148749689 S2L_SUMDATA1__57: 8 SBMU
 SG_ CellHeatMode_Status : 4|1@1+ (1,0) [0|1] ""  PC,MBMU
 SG_ CellHeatMode_PermitStatus : 22|1@1+ (1,0) [0|1] ""  PC,MBMU

BO_ 2148749690 S2L_SUMDATA1__58: 8 SBMU
 SG_ CellHeatMode_Status : 4|1@1+ (1,0) [0|1] ""  PC,MBMU
 SG_ CellHeatMode_PermitStatus : 22|1@1+ (1,0) [0|1] ""  PC,MBMU

BO_ 2148749691 S2L_SUMDATA1__59: 8 SBMU
 SG_ CellHeatMode_Status : 4|1@1+ (1,0) [0|1] ""  PC,MBMU
 SG_ CellHeatMode_PermitStatus : 22|1@1+ (1,0) [0|1] ""  PC,MBMU

BO_ 2148749692 S2L_SUMDATA1__60: 8 SBMU
 SG_ CellHeatMode_Status : 4|1@1+ (1,0) [0|1] ""  PC,MBMU
 SG_ CellHeatMode_PermitStatus : 22|1@1+ (1,0) [0|1] ""  PC,MBMU

BO_ 2148749693 S2L_SUMDATA1__61: 8 SBMU
 SG_ CellHeatMode_Status : 4|1@1+ (1,0) [0|1] ""  PC,MBMU
 SG_ CellHeatMode_PermitStatus : 22|1@1+ (1,0) [0|1] ""  PC,MBMU

BO_ 2148749694 S2L_SUMDATA1__62: 8 SBMU
 SG_ CellHeatMode_Status : 4|1@1+ (1,0) [0|1] ""  PC,MBMU
 SG_ CellHeatMode_PermitStatus : 22|1@1+ (1,0) [0|1] ""  PC,MBMU

BO_ 2148749695 S2L_SUMDATA1__63: 8 SBMU
 SG_ CellHeatMode_Status : 4|1@1+ (1,0) [0|1] ""  PC,MBMU
 SG_ CellHeatMode_PermitStatus : 22|1@1+ (1,0) [0|1] ""  PC,MBMU

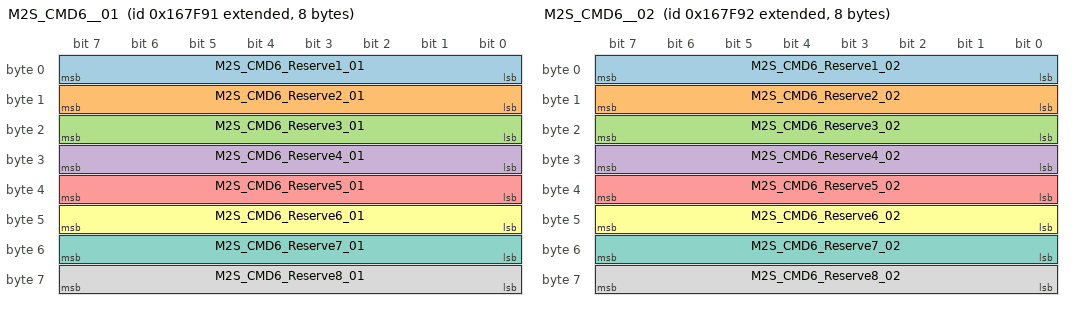
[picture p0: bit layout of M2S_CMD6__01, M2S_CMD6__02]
BO_ 2148958097 M2S_CMD6__01: 8 MBMU
 SG_ M2S_CMD6_Reserve1_01 : 0|8@1+ (1,0) [0|255] ""  SBMU
 SG_ M2S_CMD6_Reserve2_01 : 8|8@1+ (1,0) [0|255] ""  SBMU
 SG_ M2S_CMD6_Reserve3_01 : 16|8@1+ (1,0) [0|255] ""  SBMU
 SG_ M2S_CMD6_Reserve4_01 : 24|8@1+ (1,0) [0|255] ""  SBMU
 SG_ M2S_CMD6_Reserve5_01 : 32|8@1+ (1,0) [0|255] ""  SBMU
 SG_ M2S_CMD6_Reserve6_01 : 40|8@1+ (1,0) [0|255] ""  SBMU
 SG_ M2S_CMD6_Reserve7_01 : 48|8@1+ (1,0) [0|255] ""  SBMU
 SG_ M2S_CMD6_Reserve8_01 : 56|8@1+ (1,0) [0|255] ""  SBMU

BO_ 2148958098 M2S_CMD6__02: 8 MBMU
 SG_ M2S_CMD6_Reserve1_02 : 0|8@1+ (1,0) [0|255] ""  SBMU
 SG_ M2S_CMD6_Reserve2_02 : 8|8@1+ (1,0) [0|255] ""  SBMU
 SG_ M2S_CMD6_Reserve3_02 : 16|8@1+ (1,0) [0|255] ""  SBMU
 SG_ M2S_CMD6_Reserve4_02 : 24|8@1+ (1,0) [0|255] ""  SBMU
 SG_ M2S_CMD6_Reserve5_02 : 32|8@1+ (1,0) [0|255] ""  SBMU
 SG_ M2S_CMD6_Reserve6_02 : 40|8@1+ (1,0) [0|255] ""  SBMU
 SG_ M2S_CMD6_Reserve7_02 : 48|8@1+ (1,0) [0|255] ""  SBMU
 SG_ M2S_CMD6_Reserve8_02 : 56|8@1+ (1,0) [0|255] ""  SBMU

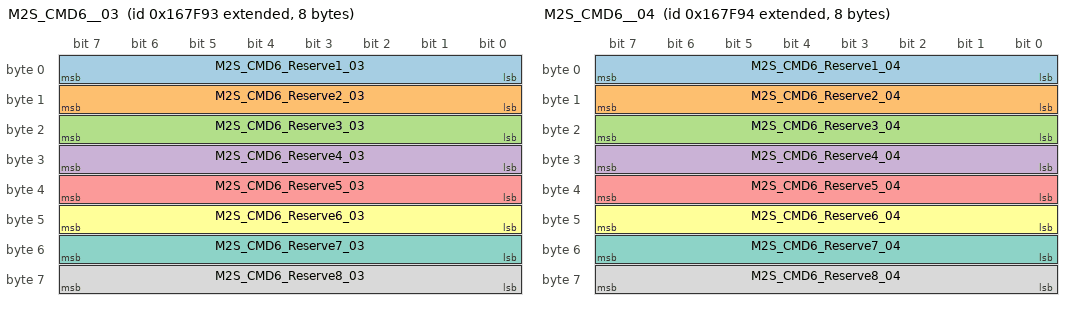
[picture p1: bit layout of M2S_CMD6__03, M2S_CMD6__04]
BO_ 2148958099 M2S_CMD6__03: 8 MBMU
 SG_ M2S_CMD6_Reserve1_03 : 0|8@1+ (1,0) [0|255] ""  SBMU
 SG_ M2S_CMD6_Reserve2_03 : 8|8@1+ (1,0) [0|255] ""  SBMU
 SG_ M2S_CMD6_Reserve3_03 : 16|8@1+ (1,0) [0|255] ""  SBMU
 SG_ M2S_CMD6_Reserve4_03 : 24|8@1+ (1,0) [0|255] ""  SBMU
 SG_ M2S_CMD6_Reserve5_03 : 32|8@1+ (1,0) [0|255] ""  SBMU
 SG_ M2S_CMD6_Reserve6_03 : 40|8@1+ (1,0) [0|255] ""  SBMU
 SG_ M2S_CMD6_Reserve7_03 : 48|8@1+ (1,0) [0|255] ""  SBMU
 SG_ M2S_CMD6_Reserve8_03 : 56|8@1+ (1,0) [0|255] ""  SBMU

BO_ 2148958100 M2S_CMD6__04: 8 MBMU
 SG_ M2S_CMD6_Reserve1_04 : 0|8@1+ (1,0) [0|255] ""  SBMU
 SG_ M2S_CMD6_Reserve2_04 : 8|8@1+ (1,0) [0|255] ""  SBMU
 SG_ M2S_CMD6_Reserve3_04 : 16|8@1+ (1,0) [0|255] ""  SBMU
 SG_ M2S_CMD6_Reserve4_04 : 24|8@1+ (1,0) [0|255] ""  SBMU
 SG_ M2S_CMD6_Reserve5_04 : 32|8@1+ (1,0) [0|255] ""  SBMU
 SG_ M2S_CMD6_Reserve6_04 : 40|8@1+ (1,0) [0|255] ""  SBMU
 SG_ M2S_CMD6_Reserve7_04 : 48|8@1+ (1,0) [0|255] ""  SBMU
 SG_ M2S_CMD6_Reserve8_04 : 56|8@1+ (1,0) [0|255] ""  SBMU

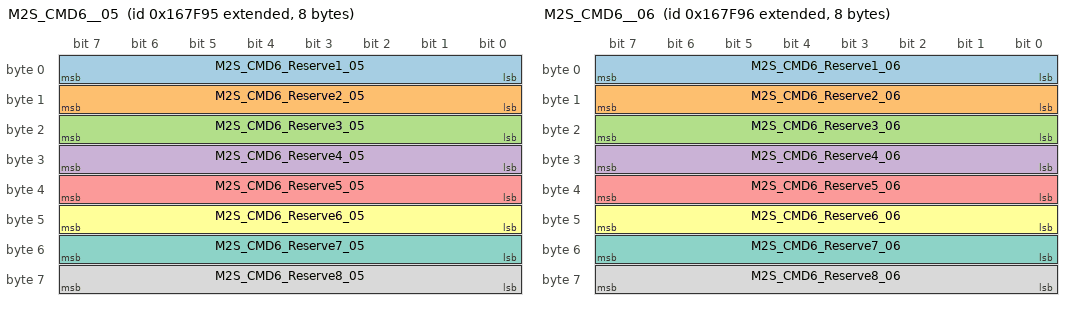
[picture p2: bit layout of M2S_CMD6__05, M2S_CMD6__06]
BO_ 2148958101 M2S_CMD6__05: 8 MBMU
 SG_ M2S_CMD6_Reserve1_05 : 0|8@1+ (1,0) [0|255] ""  SBMU
 SG_ M2S_CMD6_Reserve2_05 : 8|8@1+ (1,0) [0|255] ""  SBMU
 SG_ M2S_CMD6_Reserve3_05 : 16|8@1+ (1,0) [0|255] ""  SBMU
 SG_ M2S_CMD6_Reserve4_05 : 24|8@1+ (1,0) [0|255] ""  SBMU
 SG_ M2S_CMD6_Reserve5_05 : 32|8@1+ (1,0) [0|255] ""  SBMU
 SG_ M2S_CMD6_Reserve6_05 : 40|8@1+ (1,0) [0|255] ""  SBMU
 SG_ M2S_CMD6_Reserve7_05 : 48|8@1+ (1,0) [0|255] ""  SBMU
 SG_ M2S_CMD6_Reserve8_05 : 56|8@1+ (1,0) [0|255] ""  SBMU

BO_ 2148958102 M2S_CMD6__06: 8 MBMU
 SG_ M2S_CMD6_Reserve1_06 : 0|8@1+ (1,0) [0|255] ""  SBMU
 SG_ M2S_CMD6_Reserve2_06 : 8|8@1+ (1,0) [0|255] ""  SBMU
 SG_ M2S_CMD6_Reserve3_06 : 16|8@1+ (1,0) [0|255] ""  SBMU
 SG_ M2S_CMD6_Reserve4_06 : 24|8@1+ (1,0) [0|255] ""  SBMU
 SG_ M2S_CMD6_Reserve5_06 : 32|8@1+ (1,0) [0|255] ""  SBMU
 SG_ M2S_CMD6_Reserve6_06 : 40|8@1+ (1,0) [0|255] ""  SBMU
 SG_ M2S_CMD6_Reserve7_06 : 48|8@1+ (1,0) [0|255] ""  SBMU
 SG_ M2S_CMD6_Reserve8_06 : 56|8@1+ (1,0) [0|255] ""  SBMU

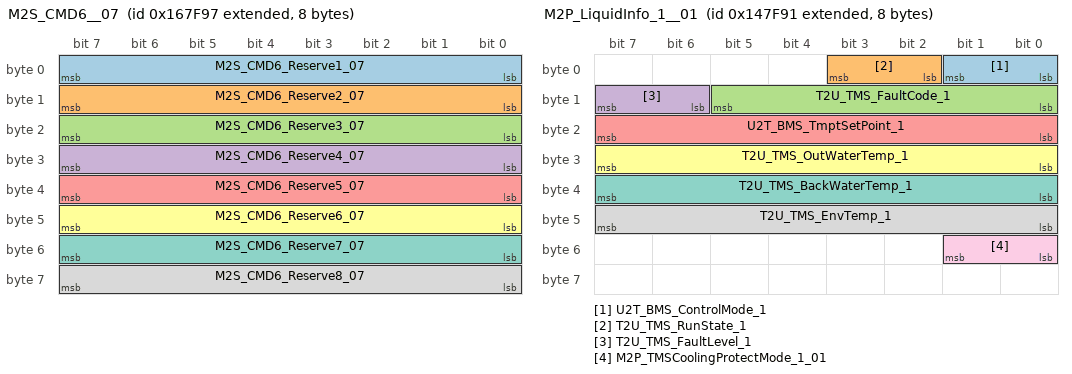
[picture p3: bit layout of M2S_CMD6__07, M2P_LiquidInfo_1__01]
BO_ 2148958103 M2S_CMD6__07: 8 MBMU
 SG_ M2S_CMD6_Reserve1_07 : 0|8@1+ (1,0) [0|255] ""  SBMU
 SG_ M2S_CMD6_Reserve2_07 : 8|8@1+ (1,0) [0|255] ""  SBMU
 SG_ M2S_CMD6_Reserve3_07 : 16|8@1+ (1,0) [0|255] ""  SBMU
 SG_ M2S_CMD6_Reserve4_07 : 24|8@1+ (1,0) [0|255] ""  SBMU
 SG_ M2S_CMD6_Reserve5_07 : 32|8@1+ (1,0) [0|255] ""  SBMU
 SG_ M2S_CMD6_Reserve6_07 : 40|8@1+ (1,0) [0|255] ""  SBMU
 SG_ M2S_CMD6_Reserve7_07 : 48|8@1+ (1,0) [0|255] ""  SBMU
 SG_ M2S_CMD6_Reserve8_07 : 56|8@1+ (1,0) [0|255] ""  SBMU

BO_ 2148958104 M2S_CMD6__08: 8 MBMU
 SG_ M2S_CMD6_Reserve1_08 : 0|8@1+ (1,0) [0|255] ""  SBMU
 SG_ M2S_CMD6_Reserve2_08 : 8|8@1+ (1,0) [0|255] ""  SBMU
 SG_ M2S_CMD6_Reserve3_08 : 16|8@1+ (1,0) [0|255] ""  SBMU
 SG_ M2S_CMD6_Reserve4_08 : 24|8@1+ (1,0) [0|255] ""  SBMU
 SG_ M2S_CMD6_Reserve5_08 : 32|8@1+ (1,0) [0|255] ""  SBMU
 SG_ M2S_CMD6_Reserve6_08 : 40|8@1+ (1,0) [0|255] ""  SBMU
 SG_ M2S_CMD6_Reserve7_08 : 48|8@1+ (1,0) [0|255] ""  SBMU
 SG_ M2S_CMD6_Reserve8_08 : 56|8@1+ (1,0) [0|255] ""  SBMU

BO_ 2148958105 M2S_CMD6__09: 8 MBMU
 SG_ M2S_CMD6_Reserve1_09 : 0|8@1+ (1,0) [0|255] ""  SBMU
 SG_ M2S_CMD6_Reserve2_09 : 8|8@1+ (1,0) [0|255] ""  SBMU
 SG_ M2S_CMD6_Reserve3_09 : 16|8@1+ (1,0) [0|255] ""  SBMU
 SG_ M2S_CMD6_Reserve4_09 : 24|8@1+ (1,0) [0|255] ""  SBMU
 SG_ M2S_CMD6_Reserve5_09 : 32|8@1+ (1,0) [0|255] ""  SBMU
 SG_ M2S_CMD6_Reserve6_09 : 40|8@1+ (1,0) [0|255] ""  SBMU
 SG_ M2S_CMD6_Reserve7_09 : 48|8@1+ (1,0) [0|255] ""  SBMU
 SG_ M2S_CMD6_Reserve8_09 : 56|8@1+ (1,0) [0|255] ""  SBMU

BO_ 2148958106 M2S_CMD6__10: 8 MBMU
 SG_ M2S_CMD6_Reserve1_10 : 0|8@1+ (1,0) [0|255] ""  SBMU
 SG_ M2S_CMD6_Reserve2_10 : 8|8@1+ (1,0) [0|255] ""  SBMU
 SG_ M2S_CMD6_Reserve3_10 : 16|8@1+ (1,0) [0|255] ""  SBMU
 SG_ M2S_CMD6_Reserve4_10 : 24|8@1+ (1,0) [0|255] ""  SBMU
 SG_ M2S_CMD6_Reserve5_10 : 32|8@1+ (1,0) [0|255] ""  SBMU
 SG_ M2S_CMD6_Reserve6_10 : 40|8@1+ (1,0) [0|255] ""  SBMU
 SG_ M2S_CMD6_Reserve7_10 : 48|8@1+ (1,0) [0|255] ""  SBMU
 SG_ M2S_CMD6_Reserve8_10 : 56|8@1+ (1,0) [0|255] ""  SBMU

BO_ 2148958107 M2S_CMD6__11: 8 MBMU
 SG_ M2S_CMD6_Reserve1_11 : 0|8@1+ (1,0) [0|255] ""  SBMU
 SG_ M2S_CMD6_Reserve2_11 : 8|8@1+ (1,0) [0|255] ""  SBMU
 SG_ M2S_CMD6_Reserve3_11 : 16|8@1+ (1,0) [0|255] ""  SBMU
 SG_ M2S_CMD6_Reserve4_11 : 24|8@1+ (1,0) [0|255] ""  SBMU
 SG_ M2S_CMD6_Reserve5_11 : 32|8@1+ (1,0) [0|255] ""  SBMU
 SG_ M2S_CMD6_Reserve6_11 : 40|8@1+ (1,0) [0|255] ""  SBMU
 SG_ M2S_CMD6_Reserve7_11 : 48|8@1+ (1,0) [0|255] ""  SBMU
 SG_ M2S_CMD6_Reserve8_11 : 56|8@1+ (1,0) [0|255] ""  SBMU

BO_ 2148958108 M2S_CMD6__12: 8 MBMU
 SG_ M2S_CMD6_Reserve1_12 : 0|8@1+ (1,0) [0|255] ""  SBMU
 SG_ M2S_CMD6_Reserve2_12 : 8|8@1+ (1,0) [0|255] ""  SBMU
 SG_ M2S_CMD6_Reserve3_12 : 16|8@1+ (1,0) [0|255] ""  SBMU
 SG_ M2S_CMD6_Reserve4_12 : 24|8@1+ (1,0) [0|255] ""  SBMU
 SG_ M2S_CMD6_Reserve5_12 : 32|8@1+ (1,0) [0|255] ""  SBMU
 SG_ M2S_CMD6_Reserve6_12 : 40|8@1+ (1,0) [0|255] ""  SBMU
 SG_ M2S_CMD6_Reserve7_12 : 48|8@1+ (1,0) [0|255] ""  SBMU
 SG_ M2S_CMD6_Reserve8_12 : 56|8@1+ (1,0) [0|255] ""  SBMU

BO_ 2148958109 M2S_CMD6__13: 8 MBMU
 SG_ M2S_CMD6_Reserve1_13 : 0|8@1+ (1,0) [0|255] ""  SBMU
 SG_ M2S_CMD6_Reserve2_13 : 8|8@1+ (1,0) [0|255] ""  SBMU
 SG_ M2S_CMD6_Reserve3_13 : 16|8@1+ (1,0) [0|255] ""  SBMU
 SG_ M2S_CMD6_Reserve4_13 : 24|8@1+ (1,0) [0|255] ""  SBMU
 SG_ M2S_CMD6_Reserve5_13 : 32|8@1+ (1,0) [0|255] ""  SBMU
 SG_ M2S_CMD6_Reserve6_13 : 40|8@1+ (1,0) [0|255] ""  SBMU
 SG_ M2S_CMD6_Reserve7_13 : 48|8@1+ (1,0) [0|255] ""  SBMU
 SG_ M2S_CMD6_Reserve8_13 : 56|8@1+ (1,0) [0|255] ""  SBMU

BO_ 2148958110 M2S_CMD6__14: 8 MBMU
 SG_ M2S_CMD6_Reserve1_14 : 0|8@1+ (1,0) [0|255] ""  SBMU
 SG_ M2S_CMD6_Reserve2_14 : 8|8@1+ (1,0) [0|255] ""  SBMU
 SG_ M2S_CMD6_Reserve3_14 : 16|8@1+ (1,0) [0|255] ""  SBMU
 SG_ M2S_CMD6_Reserve4_14 : 24|8@1+ (1,0) [0|255] ""  SBMU
 SG_ M2S_CMD6_Reserve5_14 : 32|8@1+ (1,0) [0|255] ""  SBMU
 SG_ M2S_CMD6_Reserve6_14 : 40|8@1+ (1,0) [0|255] ""  SBMU
 SG_ M2S_CMD6_Reserve7_14 : 48|8@1+ (1,0) [0|255] ""  SBMU
 SG_ M2S_CMD6_Reserve8_14 : 56|8@1+ (1,0) [0|255] ""  SBMU

BO_ 2148958111 M2S_CMD6__15: 8 MBMU
 SG_ M2S_CMD6_Reserve1_15 : 0|8@1+ (1,0) [0|255] ""  SBMU
 SG_ M2S_CMD6_Reserve2_15 : 8|8@1+ (1,0) [0|255] ""  SBMU
 SG_ M2S_CMD6_Reserve3_15 : 16|8@1+ (1,0) [0|255] ""  SBMU
 SG_ M2S_CMD6_Reserve4_15 : 24|8@1+ (1,0) [0|255] ""  SBMU
 SG_ M2S_CMD6_Reserve5_15 : 32|8@1+ (1,0) [0|255] ""  SBMU
 SG_ M2S_CMD6_Reserve6_15 : 40|8@1+ (1,0) [0|255] ""  SBMU
 SG_ M2S_CMD6_Reserve7_15 : 48|8@1+ (1,0) [0|255] ""  SBMU
 SG_ M2S_CMD6_Reserve8_15 : 56|8@1+ (1,0) [0|255] ""  SBMU

BO_ 2148958112 M2S_CMD6__16: 8 MBMU
 SG_ M2S_CMD6_Reserve1_16 : 0|8@1+ (1,0) [0|255] ""  SBMU
 SG_ M2S_CMD6_Reserve2_16 : 8|8@1+ (1,0) [0|255] ""  SBMU
 SG_ M2S_CMD6_Reserve3_16 : 16|8@1+ (1,0) [0|255] ""  SBMU
 SG_ M2S_CMD6_Reserve4_16 : 24|8@1+ (1,0) [0|255] ""  SBMU
 SG_ M2S_CMD6_Reserve5_16 : 32|8@1+ (1,0) [0|255] ""  SBMU
 SG_ M2S_CMD6_Reserve6_16 : 40|8@1+ (1,0) [0|255] ""  SBMU
 SG_ M2S_CMD6_Reserve7_16 : 48|8@1+ (1,0) [0|255] ""  SBMU
 SG_ M2S_CMD6_Reserve8_16 : 56|8@1+ (1,0) [0|255] ""  SBMU

BO_ 2148958113 M2S_CMD6__17: 8 MBMU
 SG_ M2S_CMD6_Reserve1_17 : 0|8@1+ (1,0) [0|255] ""  SBMU
 SG_ M2S_CMD6_Reserve2_17 : 8|8@1+ (1,0) [0|255] ""  SBMU
 SG_ M2S_CMD6_Reserve3_17 : 16|8@1+ (1,0) [0|255] ""  SBMU
 SG_ M2S_CMD6_Reserve4_17 : 24|8@1+ (1,0) [0|255] ""  SBMU
 SG_ M2S_CMD6_Reserve5_17 : 32|8@1+ (1,0) [0|255] ""  SBMU
 SG_ M2S_CMD6_Reserve6_17 : 40|8@1+ (1,0) [0|255] ""  SBMU
 SG_ M2S_CMD6_Reserve7_17 : 48|8@1+ (1,0) [0|255] ""  SBMU
 SG_ M2S_CMD6_Reserve8_17 : 56|8@1+ (1,0) [0|255] ""  SBMU

BO_ 2148958114 M2S_CMD6__18: 8 MBMU
 SG_ M2S_CMD6_Reserve1_18 : 0|8@1+ (1,0) [0|255] ""  SBMU
 SG_ M2S_CMD6_Reserve2_18 : 8|8@1+ (1,0) [0|255] ""  SBMU
 SG_ M2S_CMD6_Reserve3_18 : 16|8@1+ (1,0) [0|255] ""  SBMU
 SG_ M2S_CMD6_Reserve4_18 : 24|8@1+ (1,0) [0|255] ""  SBMU
 SG_ M2S_CMD6_Reserve5_18 : 32|8@1+ (1,0) [0|255] ""  SBMU
 SG_ M2S_CMD6_Reserve6_18 : 40|8@1+ (1,0) [0|255] ""  SBMU
 SG_ M2S_CMD6_Reserve7_18 : 48|8@1+ (1,0) [0|255] ""  SBMU
 SG_ M2S_CMD6_Reserve8_18 : 56|8@1+ (1,0) [0|255] ""  SBMU

BO_ 2148958115 M2S_CMD6__19: 8 MBMU
 SG_ M2S_CMD6_Reserve1_19 : 0|8@1+ (1,0) [0|255] ""  SBMU
 SG_ M2S_CMD6_Reserve2_19 : 8|8@1+ (1,0) [0|255] ""  SBMU
 SG_ M2S_CMD6_Reserve3_19 : 16|8@1+ (1,0) [0|255] ""  SBMU
 SG_ M2S_CMD6_Reserve4_19 : 24|8@1+ (1,0) [0|255] ""  SBMU
 SG_ M2S_CMD6_Reserve5_19 : 32|8@1+ (1,0) [0|255] ""  SBMU
 SG_ M2S_CMD6_Reserve6_19 : 40|8@1+ (1,0) [0|255] ""  SBMU
 SG_ M2S_CMD6_Reserve7_19 : 48|8@1+ (1,0) [0|255] ""  SBMU
 SG_ M2S_CMD6_Reserve8_19 : 56|8@1+ (1,0) [0|255] ""  SBMU

BO_ 2148958116 M2S_CMD6__20: 8 MBMU
 SG_ M2S_CMD6_Reserve1_20 : 0|8@1+ (1,0) [0|255] ""  SBMU
 SG_ M2S_CMD6_Reserve2_20 : 8|8@1+ (1,0) [0|255] ""  SBMU
 SG_ M2S_CMD6_Reserve3_20 : 16|8@1+ (1,0) [0|255] ""  SBMU
 SG_ M2S_CMD6_Reserve4_20 : 24|8@1+ (1,0) [0|255] ""  SBMU
 SG_ M2S_CMD6_Reserve5_20 : 32|8@1+ (1,0) [0|255] ""  SBMU
 SG_ M2S_CMD6_Reserve6_20 : 40|8@1+ (1,0) [0|255] ""  SBMU
 SG_ M2S_CMD6_Reserve7_20 : 48|8@1+ (1,0) [0|255] ""  SBMU
 SG_ M2S_CMD6_Reserve8_20 : 56|8@1+ (1,0) [0|255] ""  SBMU

BO_ 2148958117 M2S_CMD6__21: 8 MBMU
 SG_ M2S_CMD6_Reserve1_21 : 0|8@1+ (1,0) [0|255] ""  SBMU
 SG_ M2S_CMD6_Reserve2_21 : 8|8@1+ (1,0) [0|255] ""  SBMU
 SG_ M2S_CMD6_Reserve3_21 : 16|8@1+ (1,0) [0|255] ""  SBMU
 SG_ M2S_CMD6_Reserve4_21 : 24|8@1+ (1,0) [0|255] ""  SBMU
 SG_ M2S_CMD6_Reserve5_21 : 32|8@1+ (1,0) [0|255] ""  SBMU
 SG_ M2S_CMD6_Reserve6_21 : 40|8@1+ (1,0) [0|255] ""  SBMU
 SG_ M2S_CMD6_Reserve7_21 : 48|8@1+ (1,0) [0|255] ""  SBMU
 SG_ M2S_CMD6_Reserve8_21 : 56|8@1+ (1,0) [0|255] ""  SBMU

BO_ 2148958118 M2S_CMD6__22: 8 MBMU
 SG_ M2S_CMD6_Reserve1_22 : 0|8@1+ (1,0) [0|255] ""  SBMU
 SG_ M2S_CMD6_Reserve2_22 : 8|8@1+ (1,0) [0|255] ""  SBMU
 SG_ M2S_CMD6_Reserve3_22 : 16|8@1+ (1,0) [0|255] ""  SBMU
 SG_ M2S_CMD6_Reserve4_22 : 24|8@1+ (1,0) [0|255] ""  SBMU
 SG_ M2S_CMD6_Reserve5_22 : 32|8@1+ (1,0) [0|255] ""  SBMU
 SG_ M2S_CMD6_Reserve6_22 : 40|8@1+ (1,0) [0|255] ""  SBMU
 SG_ M2S_CMD6_Reserve7_22 : 48|8@1+ (1,0) [0|255] ""  SBMU
 SG_ M2S_CMD6_Reserve8_22 : 56|8@1+ (1,0) [0|255] ""  SBMU

BO_ 2148958119 M2S_CMD6__23: 8 MBMU
 SG_ M2S_CMD6_Reserve1_23 : 0|8@1+ (1,0) [0|255] ""  SBMU
 SG_ M2S_CMD6_Reserve2_23 : 8|8@1+ (1,0) [0|255] ""  SBMU
 SG_ M2S_CMD6_Reserve3_23 : 16|8@1+ (1,0) [0|255] ""  SBMU
 SG_ M2S_CMD6_Reserve4_23 : 24|8@1+ (1,0) [0|255] ""  SBMU
 SG_ M2S_CMD6_Reserve5_23 : 32|8@1+ (1,0) [0|255] ""  SBMU
 SG_ M2S_CMD6_Reserve6_23 : 40|8@1+ (1,0) [0|255] ""  SBMU
 SG_ M2S_CMD6_Reserve7_23 : 48|8@1+ (1,0) [0|255] ""  SBMU
 SG_ M2S_CMD6_Reserve8_23 : 56|8@1+ (1,0) [0|255] ""  SBMU

BO_ 2148958120 M2S_CMD6__24: 8 MBMU
 SG_ M2S_CMD6_Reserve1_24 : 0|8@1+ (1,0) [0|255] ""  SBMU
 SG_ M2S_CMD6_Reserve2_24 : 8|8@1+ (1,0) [0|255] ""  SBMU
 SG_ M2S_CMD6_Reserve3_24 : 16|8@1+ (1,0) [0|255] ""  SBMU
 SG_ M2S_CMD6_Reserve4_24 : 24|8@1+ (1,0) [0|255] ""  SBMU
 SG_ M2S_CMD6_Reserve5_24 : 32|8@1+ (1,0) [0|255] ""  SBMU
 SG_ M2S_CMD6_Reserve6_24 : 40|8@1+ (1,0) [0|255] ""  SBMU
 SG_ M2S_CMD6_Reserve7_24 : 48|8@1+ (1,0) [0|255] ""  SBMU
 SG_ M2S_CMD6_Reserve8_24 : 56|8@1+ (1,0) [0|255] ""  SBMU

BO_ 2148958121 M2S_CMD6__25: 8 MBMU
 SG_ M2S_CMD6_Reserve1_25 : 0|8@1+ (1,0) [0|255] ""  SBMU
 SG_ M2S_CMD6_Reserve2_25 : 8|8@1+ (1,0) [0|255] ""  SBMU
 SG_ M2S_CMD6_Reserve3_25 : 16|8@1+ (1,0) [0|255] ""  SBMU
 SG_ M2S_CMD6_Reserve4_25 : 24|8@1+ (1,0) [0|255] ""  SBMU
 SG_ M2S_CMD6_Reserve5_25 : 32|8@1+ (1,0) [0|255] ""  SBMU
 SG_ M2S_CMD6_Reserve6_25 : 40|8@1+ (1,0) [0|255] ""  SBMU
 SG_ M2S_CMD6_Reserve7_25 : 48|8@1+ (1,0) [0|255] ""  SBMU
 SG_ M2S_CMD6_Reserve8_25 : 56|8@1+ (1,0) [0|255] ""  SBMU

BO_ 2148958122 M2S_CMD6__26: 8 MBMU
 SG_ M2S_CMD6_Reserve1_26 : 0|8@1+ (1,0) [0|255] ""  SBMU
 SG_ M2S_CMD6_Reserve2_26 : 8|8@1+ (1,0) [0|255] ""  SBMU
 SG_ M2S_CMD6_Reserve3_26 : 16|8@1+ (1,0) [0|255] ""  SBMU
 SG_ M2S_CMD6_Reserve4_26 : 24|8@1+ (1,0) [0|255] ""  SBMU
 SG_ M2S_CMD6_Reserve5_26 : 32|8@1+ (1,0) [0|255] ""  SBMU
 SG_ M2S_CMD6_Reserve6_26 : 40|8@1+ (1,0) [0|255] ""  SBMU
 SG_ M2S_CMD6_Reserve7_26 : 48|8@1+ (1,0) [0|255] ""  SBMU
 SG_ M2S_CMD6_Reserve8_26 : 56|8@1+ (1,0) [0|255] ""  SBMU

BO_ 2148958123 M2S_CMD6__27: 8 MBMU
 SG_ M2S_CMD6_Reserve1_27 : 0|8@1+ (1,0) [0|255] ""  SBMU
 SG_ M2S_CMD6_Reserve2_27 : 8|8@1+ (1,0) [0|255] ""  SBMU
 SG_ M2S_CMD6_Reserve3_27 : 16|8@1+ (1,0) [0|255] ""  SBMU
 SG_ M2S_CMD6_Reserve4_27 : 24|8@1+ (1,0) [0|255] ""  SBMU
 SG_ M2S_CMD6_Reserve5_27 : 32|8@1+ (1,0) [0|255] ""  SBMU
 SG_ M2S_CMD6_Reserve6_27 : 40|8@1+ (1,0) [0|255] ""  SBMU
 SG_ M2S_CMD6_Reserve7_27 : 48|8@1+ (1,0) [0|255] ""  SBMU
 SG_ M2S_CMD6_Reserve8_27 : 56|8@1+ (1,0) [0|255] ""  SBMU

BO_ 2148958124 M2S_CMD6__28: 8 MBMU
 SG_ M2S_CMD6_Reserve1_28 : 0|8@1+ (1,0) [0|255] ""  SBMU
 SG_ M2S_CMD6_Reserve2_28 : 8|8@1+ (1,0) [0|255] ""  SBMU
 SG_ M2S_CMD6_Reserve3_28 : 16|8@1+ (1,0) [0|255] ""  SBMU
 SG_ M2S_CMD6_Reserve4_28 : 24|8@1+ (1,0) [0|255] ""  SBMU
 SG_ M2S_CMD6_Reserve5_28 : 32|8@1+ (1,0) [0|255] ""  SBMU
 SG_ M2S_CMD6_Reserve6_28 : 40|8@1+ (1,0) [0|255] ""  SBMU
 SG_ M2S_CMD6_Reserve7_28 : 48|8@1+ (1,0) [0|255] ""  SBMU
 SG_ M2S_CMD6_Reserve8_28 : 56|8@1+ (1,0) [0|255] ""  SBMU

BO_ 2148958125 M2S_CMD6__29: 8 MBMU
 SG_ M2S_CMD6_Reserve1_29 : 0|8@1+ (1,0) [0|255] ""  SBMU
 SG_ M2S_CMD6_Reserve2_29 : 8|8@1+ (1,0) [0|255] ""  SBMU
 SG_ M2S_CMD6_Reserve3_29 : 16|8@1+ (1,0) [0|255] ""  SBMU
 SG_ M2S_CMD6_Reserve4_29 : 24|8@1+ (1,0) [0|255] ""  SBMU
 SG_ M2S_CMD6_Reserve5_29 : 32|8@1+ (1,0) [0|255] ""  SBMU
 SG_ M2S_CMD6_Reserve6_29 : 40|8@1+ (1,0) [0|255] ""  SBMU
 SG_ M2S_CMD6_Reserve7_29 : 48|8@1+ (1,0) [0|255] ""  SBMU
 SG_ M2S_CMD6_Reserve8_29 : 56|8@1+ (1,0) [0|255] ""  SBMU

BO_ 2148958126 M2S_CMD6__30: 8 MBMU
 SG_ M2S_CMD6_Reserve1_30 : 0|8@1+ (1,0) [0|255] ""  SBMU
 SG_ M2S_CMD6_Reserve2_30 : 8|8@1+ (1,0) [0|255] ""  SBMU
 SG_ M2S_CMD6_Reserve3_30 : 16|8@1+ (1,0) [0|255] ""  SBMU
 SG_ M2S_CMD6_Reserve4_30 : 24|8@1+ (1,0) [0|255] ""  SBMU
 SG_ M2S_CMD6_Reserve5_30 : 32|8@1+ (1,0) [0|255] ""  SBMU
 SG_ M2S_CMD6_Reserve6_30 : 40|8@1+ (1,0) [0|255] ""  SBMU
 SG_ M2S_CMD6_Reserve7_30 : 48|8@1+ (1,0) [0|255] ""  SBMU
 SG_ M2S_CMD6_Reserve8_30 : 56|8@1+ (1,0) [0|255] ""  SBMU

BO_ 2148958127 M2S_CMD6__31: 8 MBMU
 SG_ M2S_CMD6_Reserve1_31 : 0|8@1+ (1,0) [0|255] ""  SBMU
 SG_ M2S_CMD6_Reserve2_31 : 8|8@1+ (1,0) [0|255] ""  SBMU
 SG_ M2S_CMD6_Reserve3_31 : 16|8@1+ (1,0) [0|255] ""  SBMU
 SG_ M2S_CMD6_Reserve4_31 : 24|8@1+ (1,0) [0|255] ""  SBMU
 SG_ M2S_CMD6_Reserve5_31 : 32|8@1+ (1,0) [0|255] ""  SBMU
 SG_ M2S_CMD6_Reserve6_31 : 40|8@1+ (1,0) [0|255] ""  SBMU
 SG_ M2S_CMD6_Reserve7_31 : 48|8@1+ (1,0) [0|255] ""  SBMU
 SG_ M2S_CMD6_Reserve8_31 : 56|8@1+ (1,0) [0|255] ""  SBMU

BO_ 2154921873 M2S_CMD1_CUS__01: 8 MBMU
 SG_ M2S_CMD1_CUS_Reserve1_01 : 0|8@1+ (1,0) [0|255] ""  SBMU
 SG_ M2S_CMD1_CUS_Reserve2_01 : 8|8@1+ (1,0) [0|255] ""  SBMU
 SG_ M2S_CMD1_CUS_Reserve3_01 : 16|8@1+ (1,0) [0|255] ""  SBMU
 SG_ M2S_CMD1_CUS_Reserve4_01 : 24|8@1+ (1,0) [0|255] ""  SBMU
 SG_ M2S_CMD1_CUS_Reserve5_01 : 32|8@1+ (1,0) [0|255] ""  SBMU
 SG_ M2S_CMD1_CUS_Reserve6_01 : 40|8@1+ (1,0) [0|255] ""  SBMU
 SG_ M2S_CMD1_CUS_Reserve7_01 : 48|8@1+ (1,0) [0|255] ""  SBMU
 SG_ M2S_CMD1_CUS_Reserve8_01 : 56|8@1+ (1,0) [0|255] ""  SBMU

BO_ 2154921874 M2S_CMD1_CUS__02: 8 MBMU
 SG_ M2S_CMD1_CUS_Reserve1_02 : 0|8@1+ (1,0) [0|255] ""  SBMU
 SG_ M2S_CMD1_CUS_Reserve2_02 : 8|8@1+ (1,0) [0|255] ""  SBMU
 SG_ M2S_CMD1_CUS_Reserve3_02 : 16|8@1+ (1,0) [0|255] ""  SBMU
 SG_ M2S_CMD1_CUS_Reserve4_02 : 24|8@1+ (1,0) [0|255] ""  SBMU
 SG_ M2S_CMD1_CUS_Reserve5_02 : 32|8@1+ (1,0) [0|255] ""  SBMU
 SG_ M2S_CMD1_CUS_Reserve6_02 : 40|8@1+ (1,0) [0|255] ""  SBMU
 SG_ M2S_CMD1_CUS_Reserve7_02 : 48|8@1+ (1,0) [0|255] ""  SBMU
 SG_ M2S_CMD1_CUS_Reserve8_02 : 56|8@1+ (1,0) [0|255] ""  SBMU

BO_ 2154921875 M2S_CMD1_CUS__03: 8 MBMU
 SG_ M2S_CMD1_CUS_Reserve1_03 : 0|8@1+ (1,0) [0|255] ""  SBMU
 SG_ M2S_CMD1_CUS_Reserve2_03 : 8|8@1+ (1,0) [0|255] ""  SBMU
 SG_ M2S_CMD1_CUS_Reserve3_03 : 16|8@1+ (1,0) [0|255] ""  SBMU
 SG_ M2S_CMD1_CUS_Reserve4_03 : 24|8@1+ (1,0) [0|255] ""  SBMU
 SG_ M2S_CMD1_CUS_Reserve5_03 : 32|8@1+ (1,0) [0|255] ""  SBMU
 SG_ M2S_CMD1_CUS_Reserve6_03 : 40|8@1+ (1,0) [0|255] ""  SBMU
 SG_ M2S_CMD1_CUS_Reserve7_03 : 48|8@1+ (1,0) [0|255] ""  SBMU
 SG_ M2S_CMD1_CUS_Reserve8_03 : 56|8@1+ (1,0) [0|255] ""  SBMU

BO_ 2154921876 M2S_CMD1_CUS__04: 8 MBMU
 SG_ M2S_CMD1_CUS_Reserve1_04 : 0|8@1+ (1,0) [0|255] ""  SBMU
 SG_ M2S_CMD1_CUS_Reserve2_04 : 8|8@1+ (1,0) [0|255] ""  SBMU
 SG_ M2S_CMD1_CUS_Reserve3_04 : 16|8@1+ (1,0) [0|255] ""  SBMU
 SG_ M2S_CMD1_CUS_Reserve4_04 : 24|8@1+ (1,0) [0|255] ""  SBMU
 SG_ M2S_CMD1_CUS_Reserve5_04 : 32|8@1+ (1,0) [0|255] ""  SBMU
 SG_ M2S_CMD1_CUS_Reserve6_04 : 40|8@1+ (1,0) [0|255] ""  SBMU
 SG_ M2S_CMD1_CUS_Reserve7_04 : 48|8@1+ (1,0) [0|255] ""  SBMU
 SG_ M2S_CMD1_CUS_Reserve8_04 : 56|8@1+ (1,0) [0|255] ""  SBMU

BO_ 2154921877 M2S_CMD1_CUS__05: 8 MBMU
 SG_ M2S_CMD1_CUS_Reserve1_05 : 0|8@1+ (1,0) [0|255] ""  SBMU
 SG_ M2S_CMD1_CUS_Reserve2_05 : 8|8@1+ (1,0) [0|255] ""  SBMU
 SG_ M2S_CMD1_CUS_Reserve3_05 : 16|8@1+ (1,0) [0|255] ""  SBMU
 SG_ M2S_CMD1_CUS_Reserve4_05 : 24|8@1+ (1,0) [0|255] ""  SBMU
 SG_ M2S_CMD1_CUS_Reserve5_05 : 32|8@1+ (1,0) [0|255] ""  SBMU
 SG_ M2S_CMD1_CUS_Reserve6_05 : 40|8@1+ (1,0) [0|255] ""  SBMU
 SG_ M2S_CMD1_CUS_Reserve7_05 : 48|8@1+ (1,0) [0|255] ""  SBMU
 SG_ M2S_CMD1_CUS_Reserve8_05 : 56|8@1+ (1,0) [0|255] ""  SBMU

BO_ 2154921878 M2S_CMD1_CUS__06: 8 MBMU
 SG_ M2S_CMD1_CUS_Reserve1_06 : 0|8@1+ (1,0) [0|255] ""  SBMU
 SG_ M2S_CMD1_CUS_Reserve2_06 : 8|8@1+ (1,0) [0|255] ""  SBMU
 SG_ M2S_CMD1_CUS_Reserve3_06 : 16|8@1+ (1,0) [0|255] ""  SBMU
 SG_ M2S_CMD1_CUS_Reserve4_06 : 24|8@1+ (1,0) [0|255] ""  SBMU
 SG_ M2S_CMD1_CUS_Reserve5_06 : 32|8@1+ (1,0) [0|255] ""  SBMU
 SG_ M2S_CMD1_CUS_Reserve6_06 : 40|8@1+ (1,0) [0|255] ""  SBMU
 SG_ M2S_CMD1_CUS_Reserve7_06 : 48|8@1+ (1,0) [0|255] ""  SBMU
 SG_ M2S_CMD1_CUS_Reserve8_06 : 56|8@1+ (1,0) [0|255] ""  SBMU

BO_ 2154921879 M2S_CMD1_CUS__07: 8 MBMU
 SG_ M2S_CMD1_CUS_Reserve1_07 : 0|8@1+ (1,0) [0|255] ""  SBMU
 SG_ M2S_CMD1_CUS_Reserve2_07 : 8|8@1+ (1,0) [0|255] ""  SBMU
 SG_ M2S_CMD1_CUS_Reserve3_07 : 16|8@1+ (1,0) [0|255] ""  SBMU
 SG_ M2S_CMD1_CUS_Reserve4_07 : 24|8@1+ (1,0) [0|255] ""  SBMU
 SG_ M2S_CMD1_CUS_Reserve5_07 : 32|8@1+ (1,0) [0|255] ""  SBMU
 SG_ M2S_CMD1_CUS_Reserve6_07 : 40|8@1+ (1,0) [0|255] ""  SBMU
 SG_ M2S_CMD1_CUS_Reserve7_07 : 48|8@1+ (1,0) [0|255] ""  SBMU
 SG_ M2S_CMD1_CUS_Reserve8_07 : 56|8@1+ (1,0) [0|255] ""  SBMU

BO_ 2154921880 M2S_CMD1_CUS__08: 8 MBMU
 SG_ M2S_CMD1_CUS_Reserve1_08 : 0|8@1+ (1,0) [0|255] ""  SBMU
 SG_ M2S_CMD1_CUS_Reserve2_08 : 8|8@1+ (1,0) [0|255] ""  SBMU
 SG_ M2S_CMD1_CUS_Reserve3_08 : 16|8@1+ (1,0) [0|255] ""  SBMU
 SG_ M2S_CMD1_CUS_Reserve4_08 : 24|8@1+ (1,0) [0|255] ""  SBMU
 SG_ M2S_CMD1_CUS_Reserve5_08 : 32|8@1+ (1,0) [0|255] ""  SBMU
 SG_ M2S_CMD1_CUS_Reserve6_08 : 40|8@1+ (1,0) [0|255] ""  SBMU
 SG_ M2S_CMD1_CUS_Reserve7_08 : 48|8@1+ (1,0) [0|255] ""  SBMU
 SG_ M2S_CMD1_CUS_Reserve8_08 : 56|8@1+ (1,0) [0|255] ""  SBMU

BO_ 2154921881 M2S_CMD1_CUS__09: 8 MBMU
 SG_ M2S_CMD1_CUS_Reserve1_09 : 0|8@1+ (1,0) [0|255] ""  SBMU
 SG_ M2S_CMD1_CUS_Reserve2_09 : 8|8@1+ (1,0) [0|255] ""  SBMU
 SG_ M2S_CMD1_CUS_Reserve3_09 : 16|8@1+ (1,0) [0|255] ""  SBMU
 SG_ M2S_CMD1_CUS_Reserve4_09 : 24|8@1+ (1,0) [0|255] ""  SBMU
 SG_ M2S_CMD1_CUS_Reserve5_09 : 32|8@1+ (1,0) [0|255] ""  SBMU
 SG_ M2S_CMD1_CUS_Reserve6_09 : 40|8@1+ (1,0) [0|255] ""  SBMU
 SG_ M2S_CMD1_CUS_Reserve7_09 : 48|8@1+ (1,0) [0|255] ""  SBMU
 SG_ M2S_CMD1_CUS_Reserve8_09 : 56|8@1+ (1,0) [0|255] ""  SBMU

BO_ 2154921882 M2S_CMD1_CUS__10: 8 MBMU
 SG_ M2S_CMD1_CUS_Reserve1_10 : 0|8@1+ (1,0) [0|255] ""  SBMU
 SG_ M2S_CMD1_CUS_Reserve2_10 : 8|8@1+ (1,0) [0|255] ""  SBMU
 SG_ M2S_CMD1_CUS_Reserve3_10 : 16|8@1+ (1,0) [0|255] ""  SBMU
 SG_ M2S_CMD1_CUS_Reserve4_10 : 24|8@1+ (1,0) [0|255] ""  SBMU
 SG_ M2S_CMD1_CUS_Reserve5_10 : 32|8@1+ (1,0) [0|255] ""  SBMU
 SG_ M2S_CMD1_CUS_Reserve6_10 : 40|8@1+ (1,0) [0|255] ""  SBMU
 SG_ M2S_CMD1_CUS_Reserve7_10 : 48|8@1+ (1,0) [0|255] ""  SBMU
 SG_ M2S_CMD1_CUS_Reserve8_10 : 56|8@1+ (1,0) [0|255] ""  SBMU

BO_ 2154921883 M2S_CMD1_CUS__11: 8 MBMU
 SG_ M2S_CMD1_CUS_Reserve1_11 : 0|8@1+ (1,0) [0|255] ""  SBMU
 SG_ M2S_CMD1_CUS_Reserve2_11 : 8|8@1+ (1,0) [0|255] ""  SBMU
 SG_ M2S_CMD1_CUS_Reserve3_11 : 16|8@1+ (1,0) [0|255] ""  SBMU
 SG_ M2S_CMD1_CUS_Reserve4_11 : 24|8@1+ (1,0) [0|255] ""  SBMU
 SG_ M2S_CMD1_CUS_Reserve5_11 : 32|8@1+ (1,0) [0|255] ""  SBMU
 SG_ M2S_CMD1_CUS_Reserve6_11 : 40|8@1+ (1,0) [0|255] ""  SBMU
 SG_ M2S_CMD1_CUS_Reserve7_11 : 48|8@1+ (1,0) [0|255] ""  SBMU
 SG_ M2S_CMD1_CUS_Reserve8_11 : 56|8@1+ (1,0) [0|255] ""  SBMU

BO_ 2154921884 M2S_CMD1_CUS__12: 8 MBMU
 SG_ M2S_CMD1_CUS_Reserve1_12 : 0|8@1+ (1,0) [0|255] ""  SBMU
 SG_ M2S_CMD1_CUS_Reserve2_12 : 8|8@1+ (1,0) [0|255] ""  SBMU
 SG_ M2S_CMD1_CUS_Reserve3_12 : 16|8@1+ (1,0) [0|255] ""  SBMU
 SG_ M2S_CMD1_CUS_Reserve4_12 : 24|8@1+ (1,0) [0|255] ""  SBMU
 SG_ M2S_CMD1_CUS_Reserve5_12 : 32|8@1+ (1,0) [0|255] ""  SBMU
 SG_ M2S_CMD1_CUS_Reserve6_12 : 40|8@1+ (1,0) [0|255] ""  SBMU
 SG_ M2S_CMD1_CUS_Reserve7_12 : 48|8@1+ (1,0) [0|255] ""  SBMU
 SG_ M2S_CMD1_CUS_Reserve8_12 : 56|8@1+ (1,0) [0|255] ""  SBMU

BO_ 2154921885 M2S_CMD1_CUS__13: 8 MBMU
 SG_ M2S_CMD1_CUS_Reserve1_13 : 0|8@1+ (1,0) [0|255] ""  SBMU
 SG_ M2S_CMD1_CUS_Reserve2_13 : 8|8@1+ (1,0) [0|255] ""  SBMU
 SG_ M2S_CMD1_CUS_Reserve3_13 : 16|8@1+ (1,0) [0|255] ""  SBMU
 SG_ M2S_CMD1_CUS_Reserve4_13 : 24|8@1+ (1,0) [0|255] ""  SBMU
 SG_ M2S_CMD1_CUS_Reserve5_13 : 32|8@1+ (1,0) [0|255] ""  SBMU
 SG_ M2S_CMD1_CUS_Reserve6_13 : 40|8@1+ (1,0) [0|255] ""  SBMU
 SG_ M2S_CMD1_CUS_Reserve7_13 : 48|8@1+ (1,0) [0|255] ""  SBMU
 SG_ M2S_CMD1_CUS_Reserve8_13 : 56|8@1+ (1,0) [0|255] ""  SBMU

BO_ 2154921886 M2S_CMD1_CUS__14: 8 MBMU
 SG_ M2S_CMD1_CUS_Reserve1_14 : 0|8@1+ (1,0) [0|255] ""  SBMU
 SG_ M2S_CMD1_CUS_Reserve2_14 : 8|8@1+ (1,0) [0|255] ""  SBMU
 SG_ M2S_CMD1_CUS_Reserve3_14 : 16|8@1+ (1,0) [0|255] ""  SBMU
 SG_ M2S_CMD1_CUS_Reserve4_14 : 24|8@1+ (1,0) [0|255] ""  SBMU
 SG_ M2S_CMD1_CUS_Reserve5_14 : 32|8@1+ (1,0) [0|255] ""  SBMU
 SG_ M2S_CMD1_CUS_Reserve6_14 : 40|8@1+ (1,0) [0|255] ""  SBMU
 SG_ M2S_CMD1_CUS_Reserve7_14 : 48|8@1+ (1,0) [0|255] ""  SBMU
 SG_ M2S_CMD1_CUS_Reserve8_14 : 56|8@1+ (1,0) [0|255] ""  SBMU

BO_ 2154921887 M2S_CMD1_CUS__15: 8 MBMU
 SG_ M2S_CMD1_CUS_Reserve1_15 : 0|8@1+ (1,0) [0|255] ""  SBMU
 SG_ M2S_CMD1_CUS_Reserve2_15 : 8|8@1+ (1,0) [0|255] ""  SBMU
 SG_ M2S_CMD1_CUS_Reserve3_15 : 16|8@1+ (1,0) [0|255] ""  SBMU
 SG_ M2S_CMD1_CUS_Reserve4_15 : 24|8@1+ (1,0) [0|255] ""  SBMU
 SG_ M2S_CMD1_CUS_Reserve5_15 : 32|8@1+ (1,0) [0|255] ""  SBMU
 SG_ M2S_CMD1_CUS_Reserve6_15 : 40|8@1+ (1,0) [0|255] ""  SBMU
 SG_ M2S_CMD1_CUS_Reserve7_15 : 48|8@1+ (1,0) [0|255] ""  SBMU
 SG_ M2S_CMD1_CUS_Reserve8_15 : 56|8@1+ (1,0) [0|255] ""  SBMU

BO_ 2154921888 M2S_CMD1_CUS__16: 8 MBMU
 SG_ M2S_CMD1_CUS_Reserve1_16 : 0|8@1+ (1,0) [0|255] ""  SBMU
 SG_ M2S_CMD1_CUS_Reserve2_16 : 8|8@1+ (1,0) [0|255] ""  SBMU
 SG_ M2S_CMD1_CUS_Reserve3_16 : 16|8@1+ (1,0) [0|255] ""  SBMU
 SG_ M2S_CMD1_CUS_Reserve4_16 : 24|8@1+ (1,0) [0|255] ""  SBMU
 SG_ M2S_CMD1_CUS_Reserve5_16 : 32|8@1+ (1,0) [0|255] ""  SBMU
 SG_ M2S_CMD1_CUS_Reserve6_16 : 40|8@1+ (1,0) [0|255] ""  SBMU
 SG_ M2S_CMD1_CUS_Reserve7_16 : 48|8@1+ (1,0) [0|255] ""  SBMU
 SG_ M2S_CMD1_CUS_Reserve8_16 : 56|8@1+ (1,0) [0|255] ""  SBMU

BO_ 2154921889 M2S_CMD1_CUS__17: 8 MBMU
 SG_ M2S_CMD1_CUS_Reserve1_17 : 0|8@1+ (1,0) [0|255] ""  SBMU
 SG_ M2S_CMD1_CUS_Reserve2_17 : 8|8@1+ (1,0) [0|255] ""  SBMU
 SG_ M2S_CMD1_CUS_Reserve3_17 : 16|8@1+ (1,0) [0|255] ""  SBMU
 SG_ M2S_CMD1_CUS_Reserve4_17 : 24|8@1+ (1,0) [0|255] ""  SBMU
 SG_ M2S_CMD1_CUS_Reserve5_17 : 32|8@1+ (1,0) [0|255] ""  SBMU
 SG_ M2S_CMD1_CUS_Reserve6_17 : 40|8@1+ (1,0) [0|255] ""  SBMU
 SG_ M2S_CMD1_CUS_Reserve7_17 : 48|8@1+ (1,0) [0|255] ""  SBMU
 SG_ M2S_CMD1_CUS_Reserve8_17 : 56|8@1+ (1,0) [0|255] ""  SBMU

BO_ 2154921890 M2S_CMD1_CUS__18: 8 MBMU
 SG_ M2S_CMD1_CUS_Reserve1_18 : 0|8@1+ (1,0) [0|255] ""  SBMU
 SG_ M2S_CMD1_CUS_Reserve2_18 : 8|8@1+ (1,0) [0|255] ""  SBMU
 SG_ M2S_CMD1_CUS_Reserve3_18 : 16|8@1+ (1,0) [0|255] ""  SBMU
 SG_ M2S_CMD1_CUS_Reserve4_18 : 24|8@1+ (1,0) [0|255] ""  SBMU
 SG_ M2S_CMD1_CUS_Reserve5_18 : 32|8@1+ (1,0) [0|255] ""  SBMU
 SG_ M2S_CMD1_CUS_Reserve6_18 : 40|8@1+ (1,0) [0|255] ""  SBMU
 SG_ M2S_CMD1_CUS_Reserve7_18 : 48|8@1+ (1,0) [0|255] ""  SBMU
 SG_ M2S_CMD1_CUS_Reserve8_18 : 56|8@1+ (1,0) [0|255] ""  SBMU

BO_ 2154921891 M2S_CMD1_CUS__19: 8 MBMU
 SG_ M2S_CMD1_CUS_Reserve1_19 : 0|8@1+ (1,0) [0|255] ""  SBMU
 SG_ M2S_CMD1_CUS_Reserve2_19 : 8|8@1+ (1,0) [0|255] ""  SBMU
 SG_ M2S_CMD1_CUS_Reserve3_19 : 16|8@1+ (1,0) [0|255] ""  SBMU
 SG_ M2S_CMD1_CUS_Reserve4_19 : 24|8@1+ (1,0) [0|255] ""  SBMU
 SG_ M2S_CMD1_CUS_Reserve5_19 : 32|8@1+ (1,0) [0|255] ""  SBMU
 SG_ M2S_CMD1_CUS_Reserve6_19 : 40|8@1+ (1,0) [0|255] ""  SBMU
 SG_ M2S_CMD1_CUS_Reserve7_19 : 48|8@1+ (1,0) [0|255] ""  SBMU
 SG_ M2S_CMD1_CUS_Reserve8_19 : 56|8@1+ (1,0) [0|255] ""  SBMU

BO_ 2154921892 M2S_CMD1_CUS__20: 8 MBMU
 SG_ M2S_CMD1_CUS_Reserve1_20 : 0|8@1+ (1,0) [0|255] ""  SBMU
 SG_ M2S_CMD1_CUS_Reserve2_20 : 8|8@1+ (1,0) [0|255] ""  SBMU
 SG_ M2S_CMD1_CUS_Reserve3_20 : 16|8@1+ (1,0) [0|255] ""  SBMU
 SG_ M2S_CMD1_CUS_Reserve4_20 : 24|8@1+ (1,0) [0|255] ""  SBMU
 SG_ M2S_CMD1_CUS_Reserve5_20 : 32|8@1+ (1,0) [0|255] ""  SBMU
 SG_ M2S_CMD1_CUS_Reserve6_20 : 40|8@1+ (1,0) [0|255] ""  SBMU
 SG_ M2S_CMD1_CUS_Reserve7_20 : 48|8@1+ (1,0) [0|255] ""  SBMU
 SG_ M2S_CMD1_CUS_Reserve8_20 : 56|8@1+ (1,0) [0|255] ""  SBMU

BO_ 2154921893 M2S_CMD1_CUS__21: 8 MBMU
 SG_ M2S_CMD1_CUS_Reserve1_21 : 0|8@1+ (1,0) [0|255] ""  SBMU
 SG_ M2S_CMD1_CUS_Reserve2_21 : 8|8@1+ (1,0) [0|255] ""  SBMU
 SG_ M2S_CMD1_CUS_Reserve3_21 : 16|8@1+ (1,0) [0|255] ""  SBMU
 SG_ M2S_CMD1_CUS_Reserve4_21 : 24|8@1+ (1,0) [0|255] ""  SBMU
 SG_ M2S_CMD1_CUS_Reserve5_21 : 32|8@1+ (1,0) [0|255] ""  SBMU
 SG_ M2S_CMD1_CUS_Reserve6_21 : 40|8@1+ (1,0) [0|255] ""  SBMU
 SG_ M2S_CMD1_CUS_Reserve7_21 : 48|8@1+ (1,0) [0|255] ""  SBMU
 SG_ M2S_CMD1_CUS_Reserve8_21 : 56|8@1+ (1,0) [0|255] ""  SBMU

BO_ 2154921894 M2S_CMD1_CUS__22: 8 MBMU
 SG_ M2S_CMD1_CUS_Reserve1_22 : 0|8@1+ (1,0) [0|255] ""  SBMU
 SG_ M2S_CMD1_CUS_Reserve2_22 : 8|8@1+ (1,0) [0|255] ""  SBMU
 SG_ M2S_CMD1_CUS_Reserve3_22 : 16|8@1+ (1,0) [0|255] ""  SBMU
 SG_ M2S_CMD1_CUS_Reserve4_22 : 24|8@1+ (1,0) [0|255] ""  SBMU
 SG_ M2S_CMD1_CUS_Reserve5_22 : 32|8@1+ (1,0) [0|255] ""  SBMU
 SG_ M2S_CMD1_CUS_Reserve6_22 : 40|8@1+ (1,0) [0|255] ""  SBMU
 SG_ M2S_CMD1_CUS_Reserve7_22 : 48|8@1+ (1,0) [0|255] ""  SBMU
 SG_ M2S_CMD1_CUS_Reserve8_22 : 56|8@1+ (1,0) [0|255] ""  SBMU

BO_ 2154921895 M2S_CMD1_CUS__23: 8 MBMU
 SG_ M2S_CMD1_CUS_Reserve1_23 : 0|8@1+ (1,0) [0|255] ""  SBMU
 SG_ M2S_CMD1_CUS_Reserve2_23 : 8|8@1+ (1,0) [0|255] ""  SBMU
 SG_ M2S_CMD1_CUS_Reserve3_23 : 16|8@1+ (1,0) [0|255] ""  SBMU
 SG_ M2S_CMD1_CUS_Reserve4_23 : 24|8@1+ (1,0) [0|255] ""  SBMU
 SG_ M2S_CMD1_CUS_Reserve5_23 : 32|8@1+ (1,0) [0|255] ""  SBMU
 SG_ M2S_CMD1_CUS_Reserve6_23 : 40|8@1+ (1,0) [0|255] ""  SBMU
 SG_ M2S_CMD1_CUS_Reserve7_23 : 48|8@1+ (1,0) [0|255] ""  SBMU
 SG_ M2S_CMD1_CUS_Reserve8_23 : 56|8@1+ (1,0) [0|255] ""  SBMU

BO_ 2154921896 M2S_CMD1_CUS__24: 8 MBMU
 SG_ M2S_CMD1_CUS_Reserve1_24 : 0|8@1+ (1,0) [0|255] ""  SBMU
 SG_ M2S_CMD1_CUS_Reserve2_24 : 8|8@1+ (1,0) [0|255] ""  SBMU
 SG_ M2S_CMD1_CUS_Reserve3_24 : 16|8@1+ (1,0) [0|255] ""  SBMU
 SG_ M2S_CMD1_CUS_Reserve4_24 : 24|8@1+ (1,0) [0|255] ""  SBMU
 SG_ M2S_CMD1_CUS_Reserve5_24 : 32|8@1+ (1,0) [0|255] ""  SBMU
 SG_ M2S_CMD1_CUS_Reserve6_24 : 40|8@1+ (1,0) [0|255] ""  SBMU
 SG_ M2S_CMD1_CUS_Reserve7_24 : 48|8@1+ (1,0) [0|255] ""  SBMU
 SG_ M2S_CMD1_CUS_Reserve8_24 : 56|8@1+ (1,0) [0|255] ""  SBMU

BO_ 2154921897 M2S_CMD1_CUS__25: 8 MBMU
 SG_ M2S_CMD1_CUS_Reserve1_25 : 0|8@1+ (1,0) [0|255] ""  SBMU
 SG_ M2S_CMD1_CUS_Reserve2_25 : 8|8@1+ (1,0) [0|255] ""  SBMU
 SG_ M2S_CMD1_CUS_Reserve3_25 : 16|8@1+ (1,0) [0|255] ""  SBMU
 SG_ M2S_CMD1_CUS_Reserve4_25 : 24|8@1+ (1,0) [0|255] ""  SBMU
 SG_ M2S_CMD1_CUS_Reserve5_25 : 32|8@1+ (1,0) [0|255] ""  SBMU
 SG_ M2S_CMD1_CUS_Reserve6_25 : 40|8@1+ (1,0) [0|255] ""  SBMU
 SG_ M2S_CMD1_CUS_Reserve7_25 : 48|8@1+ (1,0) [0|255] ""  SBMU
 SG_ M2S_CMD1_CUS_Reserve8_25 : 56|8@1+ (1,0) [0|255] ""  SBMU

BO_ 2154921898 M2S_CMD1_CUS__26: 8 MBMU
 SG_ M2S_CMD1_CUS_Reserve1_26 : 0|8@1+ (1,0) [0|255] ""  SBMU
 SG_ M2S_CMD1_CUS_Reserve2_26 : 8|8@1+ (1,0) [0|255] ""  SBMU
 SG_ M2S_CMD1_CUS_Reserve3_26 : 16|8@1+ (1,0) [0|255] ""  SBMU
 SG_ M2S_CMD1_CUS_Reserve4_26 : 24|8@1+ (1,0) [0|255] ""  SBMU
 SG_ M2S_CMD1_CUS_Reserve5_26 : 32|8@1+ (1,0) [0|255] ""  SBMU
 SG_ M2S_CMD1_CUS_Reserve6_26 : 40|8@1+ (1,0) [0|255] ""  SBMU
 SG_ M2S_CMD1_CUS_Reserve7_26 : 48|8@1+ (1,0) [0|255] ""  SBMU
 SG_ M2S_CMD1_CUS_Reserve8_26 : 56|8@1+ (1,0) [0|255] ""  SBMU

BO_ 2154921899 M2S_CMD1_CUS__27: 8 MBMU
 SG_ M2S_CMD1_CUS_Reserve1_27 : 0|8@1+ (1,0) [0|255] ""  SBMU
 SG_ M2S_CMD1_CUS_Reserve2_27 : 8|8@1+ (1,0) [0|255] ""  SBMU
 SG_ M2S_CMD1_CUS_Reserve3_27 : 16|8@1+ (1,0) [0|255] ""  SBMU
 SG_ M2S_CMD1_CUS_Reserve4_27 : 24|8@1+ (1,0) [0|255] ""  SBMU
 SG_ M2S_CMD1_CUS_Reserve5_27 : 32|8@1+ (1,0) [0|255] ""  SBMU
 SG_ M2S_CMD1_CUS_Reserve6_27 : 40|8@1+ (1,0) [0|255] ""  SBMU
 SG_ M2S_CMD1_CUS_Reserve7_27 : 48|8@1+ (1,0) [0|255] ""  SBMU
 SG_ M2S_CMD1_CUS_Reserve8_27 : 56|8@1+ (1,0) [0|255] ""  SBMU

BO_ 2154921900 M2S_CMD1_CUS__28: 8 MBMU
 SG_ M2S_CMD1_CUS_Reserve1_28 : 0|8@1+ (1,0) [0|255] ""  SBMU
 SG_ M2S_CMD1_CUS_Reserve2_28 : 8|8@1+ (1,0) [0|255] ""  SBMU
 SG_ M2S_CMD1_CUS_Reserve3_28 : 16|8@1+ (1,0) [0|255] ""  SBMU
 SG_ M2S_CMD1_CUS_Reserve4_28 : 24|8@1+ (1,0) [0|255] ""  SBMU
 SG_ M2S_CMD1_CUS_Reserve5_28 : 32|8@1+ (1,0) [0|255] ""  SBMU
 SG_ M2S_CMD1_CUS_Reserve6_28 : 40|8@1+ (1,0) [0|255] ""  SBMU
 SG_ M2S_CMD1_CUS_Reserve7_28 : 48|8@1+ (1,0) [0|255] ""  SBMU
 SG_ M2S_CMD1_CUS_Reserve8_28 : 56|8@1+ (1,0) [0|255] ""  SBMU

BO_ 2154921901 M2S_CMD1_CUS__29: 8 MBMU
 SG_ M2S_CMD1_CUS_Reserve1_29 : 0|8@1+ (1,0) [0|255] ""  SBMU
 SG_ M2S_CMD1_CUS_Reserve2_29 : 8|8@1+ (1,0) [0|255] ""  SBMU
 SG_ M2S_CMD1_CUS_Reserve3_29 : 16|8@1+ (1,0) [0|255] ""  SBMU
 SG_ M2S_CMD1_CUS_Reserve4_29 : 24|8@1+ (1,0) [0|255] ""  SBMU
 SG_ M2S_CMD1_CUS_Reserve5_29 : 32|8@1+ (1,0) [0|255] ""  SBMU
 SG_ M2S_CMD1_CUS_Reserve6_29 : 40|8@1+ (1,0) [0|255] ""  SBMU
 SG_ M2S_CMD1_CUS_Reserve7_29 : 48|8@1+ (1,0) [0|255] ""  SBMU
 SG_ M2S_CMD1_CUS_Reserve8_29 : 56|8@1+ (1,0) [0|255] ""  SBMU

BO_ 2154921902 M2S_CMD1_CUS__30: 8 MBMU
 SG_ M2S_CMD1_CUS_Reserve1_30 : 0|8@1+ (1,0) [0|255] ""  SBMU
 SG_ M2S_CMD1_CUS_Reserve2_30 : 8|8@1+ (1,0) [0|255] ""  SBMU
 SG_ M2S_CMD1_CUS_Reserve3_30 : 16|8@1+ (1,0) [0|255] ""  SBMU
 SG_ M2S_CMD1_CUS_Reserve4_30 : 24|8@1+ (1,0) [0|255] ""  SBMU
 SG_ M2S_CMD1_CUS_Reserve5_30 : 32|8@1+ (1,0) [0|255] ""  SBMU
 SG_ M2S_CMD1_CUS_Reserve6_30 : 40|8@1+ (1,0) [0|255] ""  SBMU
 SG_ M2S_CMD1_CUS_Reserve7_30 : 48|8@1+ (1,0) [0|255] ""  SBMU
 SG_ M2S_CMD1_CUS_Reserve8_30 : 56|8@1+ (1,0) [0|255] ""  SBMU

BO_ 2154921903 M2S_CMD1_CUS__31: 8 MBMU
 SG_ M2S_CMD1_CUS_Reserve1_31 : 0|8@1+ (1,0) [0|255] ""  SBMU
 SG_ M2S_CMD1_CUS_Reserve2_31 : 8|8@1+ (1,0) [0|255] ""  SBMU
 SG_ M2S_CMD1_CUS_Reserve3_31 : 16|8@1+ (1,0) [0|255] ""  SBMU
 SG_ M2S_CMD1_CUS_Reserve4_31 : 24|8@1+ (1,0) [0|255] ""  SBMU
 SG_ M2S_CMD1_CUS_Reserve5_31 : 32|8@1+ (1,0) [0|255] ""  SBMU
 SG_ M2S_CMD1_CUS_Reserve6_31 : 40|8@1+ (1,0) [0|255] ""  SBMU
 SG_ M2S_CMD1_CUS_Reserve7_31 : 48|8@1+ (1,0) [0|255] ""  SBMU
 SG_ M2S_CMD1_CUS_Reserve8_31 : 56|8@1+ (1,0) [0|255] ""  SBMU

BO_ 2154987409 M2S_CMD2_CUS__01: 8 MBMU
 SG_ M2S_CMD2_CUS_Reserve1_01 : 0|8@1+ (1,0) [0|255] ""  SBMU
 SG_ M2S_CMD2_CUS_Reserve2_01 : 8|8@1+ (1,0) [0|255] ""  SBMU
 SG_ M2S_CMD2_CUS_Reserve3_01 : 16|8@1+ (1,0) [0|255] ""  SBMU
 SG_ M2S_CMD2_CUS_Reserve4_01 : 24|8@1+ (1,0) [0|255] ""  SBMU
 SG_ M2S_CMD2_CUS_Reserve5_01 : 32|8@1+ (1,0) [0|255] ""  SBMU
 SG_ M2S_CMD2_CUS_Reserve6_01 : 40|8@1+ (1,0) [0|255] ""  SBMU
 SG_ M2S_CMD2_CUS_Reserve7_01 : 48|8@1+ (1,0) [0|255] ""  SBMU
 SG_ M2S_CMD2_CUS_Reserve8_01 : 56|8@1+ (1,0) [0|255] ""  SBMU

BO_ 2154987410 M2S_CMD2_CUS__02: 8 MBMU
 SG_ M2S_CMD2_CUS_Reserve1_02 : 0|8@1+ (1,0) [0|255] ""  SBMU
 SG_ M2S_CMD2_CUS_Reserve2_02 : 8|8@1+ (1,0) [0|255] ""  SBMU
 SG_ M2S_CMD2_CUS_Reserve3_02 : 16|8@1+ (1,0) [0|255] ""  SBMU
 SG_ M2S_CMD2_CUS_Reserve4_02 : 24|8@1+ (1,0) [0|255] ""  SBMU
 SG_ M2S_CMD2_CUS_Reserve5_02 : 32|8@1+ (1,0) [0|255] ""  SBMU
 SG_ M2S_CMD2_CUS_Reserve6_02 : 40|8@1+ (1,0) [0|255] ""  SBMU
 SG_ M2S_CMD2_CUS_Reserve7_02 : 48|8@1+ (1,0) [0|255] ""  SBMU
 SG_ M2S_CMD2_CUS_Reserve8_02 : 56|8@1+ (1,0) [0|255] ""  SBMU

BO_ 2154987411 M2S_CMD2_CUS__03: 8 MBMU
 SG_ M2S_CMD2_CUS_Reserve1_03 : 0|8@1+ (1,0) [0|255] ""  SBMU
 SG_ M2S_CMD2_CUS_Reserve2_03 : 8|8@1+ (1,0) [0|255] ""  SBMU
 SG_ M2S_CMD2_CUS_Reserve3_03 : 16|8@1+ (1,0) [0|255] ""  SBMU
 SG_ M2S_CMD2_CUS_Reserve4_03 : 24|8@1+ (1,0) [0|255] ""  SBMU
 SG_ M2S_CMD2_CUS_Reserve5_03 : 32|8@1+ (1,0) [0|255] ""  SBMU
 SG_ M2S_CMD2_CUS_Reserve6_03 : 40|8@1+ (1,0) [0|255] ""  SBMU
 SG_ M2S_CMD2_CUS_Reserve7_03 : 48|8@1+ (1,0) [0|255] ""  SBMU
 SG_ M2S_CMD2_CUS_Reserve8_03 : 56|8@1+ (1,0) [0|255] ""  SBMU

BO_ 2154987412 M2S_CMD2_CUS__04: 8 MBMU
 SG_ M2S_CMD2_CUS_Reserve1_04 : 0|8@1+ (1,0) [0|255] ""  SBMU
 SG_ M2S_CMD2_CUS_Reserve2_04 : 8|8@1+ (1,0) [0|255] ""  SBMU
 SG_ M2S_CMD2_CUS_Reserve3_04 : 16|8@1+ (1,0) [0|255] ""  SBMU
 SG_ M2S_CMD2_CUS_Reserve4_04 : 24|8@1+ (1,0) [0|255] ""  SBMU
 SG_ M2S_CMD2_CUS_Reserve5_04 : 32|8@1+ (1,0) [0|255] ""  SBMU
 SG_ M2S_CMD2_CUS_Reserve6_04 : 40|8@1+ (1,0) [0|255] ""  SBMU
 SG_ M2S_CMD2_CUS_Reserve7_04 : 48|8@1+ (1,0) [0|255] ""  SBMU
 SG_ M2S_CMD2_CUS_Reserve8_04 : 56|8@1+ (1,0) [0|255] ""  SBMU

BO_ 2154987413 M2S_CMD2_CUS__05: 8 MBMU
 SG_ M2S_CMD2_CUS_Reserve1_05 : 0|8@1+ (1,0) [0|255] ""  SBMU
 SG_ M2S_CMD2_CUS_Reserve2_05 : 8|8@1+ (1,0) [0|255] ""  SBMU
 SG_ M2S_CMD2_CUS_Reserve3_05 : 16|8@1+ (1,0) [0|255] ""  SBMU
 SG_ M2S_CMD2_CUS_Reserve4_05 : 24|8@1+ (1,0) [0|255] ""  SBMU
 SG_ M2S_CMD2_CUS_Reserve5_05 : 32|8@1+ (1,0) [0|255] ""  SBMU
 SG_ M2S_CMD2_CUS_Reserve6_05 : 40|8@1+ (1,0) [0|255] ""  SBMU
 SG_ M2S_CMD2_CUS_Reserve7_05 : 48|8@1+ (1,0) [0|255] ""  SBMU
 SG_ M2S_CMD2_CUS_Reserve8_05 : 56|8@1+ (1,0) [0|255] ""  SBMU

BO_ 2154987414 M2S_CMD2_CUS__06: 8 MBMU
 SG_ M2S_CMD2_CUS_Reserve1_06 : 0|8@1+ (1,0) [0|255] ""  SBMU
 SG_ M2S_CMD2_CUS_Reserve2_06 : 8|8@1+ (1,0) [0|255] ""  SBMU
 SG_ M2S_CMD2_CUS_Reserve3_06 : 16|8@1+ (1,0) [0|255] ""  SBMU
 SG_ M2S_CMD2_CUS_Reserve4_06 : 24|8@1+ (1,0) [0|255] ""  SBMU
 SG_ M2S_CMD2_CUS_Reserve5_06 : 32|8@1+ (1,0) [0|255] ""  SBMU
 SG_ M2S_CMD2_CUS_Reserve6_06 : 40|8@1+ (1,0) [0|255] ""  SBMU
 SG_ M2S_CMD2_CUS_Reserve7_06 : 48|8@1+ (1,0) [0|255] ""  SBMU
 SG_ M2S_CMD2_CUS_Reserve8_06 : 56|8@1+ (1,0) [0|255] ""  SBMU

BO_ 2154987415 M2S_CMD2_CUS__07: 8 MBMU
 SG_ M2S_CMD2_CUS_Reserve1_07 : 0|8@1+ (1,0) [0|255] ""  SBMU
 SG_ M2S_CMD2_CUS_Reserve2_07 : 8|8@1+ (1,0) [0|255] ""  SBMU
 SG_ M2S_CMD2_CUS_Reserve3_07 : 16|8@1+ (1,0) [0|255] ""  SBMU
 SG_ M2S_CMD2_CUS_Reserve4_07 : 24|8@1+ (1,0) [0|255] ""  SBMU
 SG_ M2S_CMD2_CUS_Reserve5_07 : 32|8@1+ (1,0) [0|255] ""  SBMU
 SG_ M2S_CMD2_CUS_Reserve6_07 : 40|8@1+ (1,0) [0|255] ""  SBMU
 SG_ M2S_CMD2_CUS_Reserve7_07 : 48|8@1+ (1,0) [0|255] ""  SBMU
 SG_ M2S_CMD2_CUS_Reserve8_07 : 56|8@1+ (1,0) [0|255] ""  SBMU

BO_ 2154987416 M2S_CMD2_CUS__08: 8 MBMU
 SG_ M2S_CMD2_CUS_Reserve1_08 : 0|8@1+ (1,0) [0|255] ""  SBMU
 SG_ M2S_CMD2_CUS_Reserve2_08 : 8|8@1+ (1,0) [0|255] ""  SBMU
 SG_ M2S_CMD2_CUS_Reserve3_08 : 16|8@1+ (1,0) [0|255] ""  SBMU
 SG_ M2S_CMD2_CUS_Reserve4_08 : 24|8@1+ (1,0) [0|255] ""  SBMU
 SG_ M2S_CMD2_CUS_Reserve5_08 : 32|8@1+ (1,0) [0|255] ""  SBMU
 SG_ M2S_CMD2_CUS_Reserve6_08 : 40|8@1+ (1,0) [0|255] ""  SBMU
 SG_ M2S_CMD2_CUS_Reserve7_08 : 48|8@1+ (1,0) [0|255] ""  SBMU
 SG_ M2S_CMD2_CUS_Reserve8_08 : 56|8@1+ (1,0) [0|255] ""  SBMU

BO_ 2154987417 M2S_CMD2_CUS__09: 8 MBMU
 SG_ M2S_CMD2_CUS_Reserve1_09 : 0|8@1+ (1,0) [0|255] ""  SBMU
 SG_ M2S_CMD2_CUS_Reserve2_09 : 8|8@1+ (1,0) [0|255] ""  SBMU
 SG_ M2S_CMD2_CUS_Reserve3_09 : 16|8@1+ (1,0) [0|255] ""  SBMU
 SG_ M2S_CMD2_CUS_Reserve4_09 : 24|8@1+ (1,0) [0|255] ""  SBMU
 SG_ M2S_CMD2_CUS_Reserve5_09 : 32|8@1+ (1,0) [0|255] ""  SBMU
 SG_ M2S_CMD2_CUS_Reserve6_09 : 40|8@1+ (1,0) [0|255] ""  SBMU
 SG_ M2S_CMD2_CUS_Reserve7_09 : 48|8@1+ (1,0) [0|255] ""  SBMU
 SG_ M2S_CMD2_CUS_Reserve8_09 : 56|8@1+ (1,0) [0|255] ""  SBMU

BO_ 2154987418 M2S_CMD2_CUS__10: 8 MBMU
 SG_ M2S_CMD2_CUS_Reserve1_10 : 0|8@1+ (1,0) [0|255] ""  SBMU
 SG_ M2S_CMD2_CUS_Reserve2_10 : 8|8@1+ (1,0) [0|255] ""  SBMU
 SG_ M2S_CMD2_CUS_Reserve3_10 : 16|8@1+ (1,0) [0|255] ""  SBMU
 SG_ M2S_CMD2_CUS_Reserve4_10 : 24|8@1+ (1,0) [0|255] ""  SBMU
 SG_ M2S_CMD2_CUS_Reserve5_10 : 32|8@1+ (1,0) [0|255] ""  SBMU
 SG_ M2S_CMD2_CUS_Reserve6_10 : 40|8@1+ (1,0) [0|255] ""  SBMU
 SG_ M2S_CMD2_CUS_Reserve7_10 : 48|8@1+ (1,0) [0|255] ""  SBMU
 SG_ M2S_CMD2_CUS_Reserve8_10 : 56|8@1+ (1,0) [0|255] ""  SBMU

BO_ 2154987419 M2S_CMD2_CUS__11: 8 MBMU
 SG_ M2S_CMD2_CUS_Reserve1_11 : 0|8@1+ (1,0) [0|255] ""  SBMU
 SG_ M2S_CMD2_CUS_Reserve2_11 : 8|8@1+ (1,0) [0|255] ""  SBMU
 SG_ M2S_CMD2_CUS_Reserve3_11 : 16|8@1+ (1,0) [0|255] ""  SBMU
 SG_ M2S_CMD2_CUS_Reserve4_11 : 24|8@1+ (1,0) [0|255] ""  SBMU
 SG_ M2S_CMD2_CUS_Reserve5_11 : 32|8@1+ (1,0) [0|255] ""  SBMU
 SG_ M2S_CMD2_CUS_Reserve6_11 : 40|8@1+ (1,0) [0|255] ""  SBMU
 SG_ M2S_CMD2_CUS_Reserve7_11 : 48|8@1+ (1,0) [0|255] ""  SBMU
 SG_ M2S_CMD2_CUS_Reserve8_11 : 56|8@1+ (1,0) [0|255] ""  SBMU

BO_ 2154987420 M2S_CMD2_CUS__12: 8 MBMU
 SG_ M2S_CMD2_CUS_Reserve1_12 : 0|8@1+ (1,0) [0|255] ""  SBMU
 SG_ M2S_CMD2_CUS_Reserve2_12 : 8|8@1+ (1,0) [0|255] ""  SBMU
 SG_ M2S_CMD2_CUS_Reserve3_12 : 16|8@1+ (1,0) [0|255] ""  SBMU
 SG_ M2S_CMD2_CUS_Reserve4_12 : 24|8@1+ (1,0) [0|255] ""  SBMU
 SG_ M2S_CMD2_CUS_Reserve5_12 : 32|8@1+ (1,0) [0|255] ""  SBMU
 SG_ M2S_CMD2_CUS_Reserve6_12 : 40|8@1+ (1,0) [0|255] ""  SBMU
 SG_ M2S_CMD2_CUS_Reserve7_12 : 48|8@1+ (1,0) [0|255] ""  SBMU
 SG_ M2S_CMD2_CUS_Reserve8_12 : 56|8@1+ (1,0) [0|255] ""  SBMU

BO_ 2154987421 M2S_CMD2_CUS__13: 8 MBMU
 SG_ M2S_CMD2_CUS_Reserve1_13 : 0|8@1+ (1,0) [0|255] ""  SBMU
 SG_ M2S_CMD2_CUS_Reserve2_13 : 8|8@1+ (1,0) [0|255] ""  SBMU
 SG_ M2S_CMD2_CUS_Reserve3_13 : 16|8@1+ (1,0) [0|255] ""  SBMU
 SG_ M2S_CMD2_CUS_Reserve4_13 : 24|8@1+ (1,0) [0|255] ""  SBMU
 SG_ M2S_CMD2_CUS_Reserve5_13 : 32|8@1+ (1,0) [0|255] ""  SBMU
 SG_ M2S_CMD2_CUS_Reserve6_13 : 40|8@1+ (1,0) [0|255] ""  SBMU
 SG_ M2S_CMD2_CUS_Reserve7_13 : 48|8@1+ (1,0) [0|255] ""  SBMU
 SG_ M2S_CMD2_CUS_Reserve8_13 : 56|8@1+ (1,0) [0|255] ""  SBMU

BO_ 2154987422 M2S_CMD2_CUS__14: 8 MBMU
 SG_ M2S_CMD2_CUS_Reserve1_14 : 0|8@1+ (1,0) [0|255] ""  SBMU
 SG_ M2S_CMD2_CUS_Reserve2_14 : 8|8@1+ (1,0) [0|255] ""  SBMU
 SG_ M2S_CMD2_CUS_Reserve3_14 : 16|8@1+ (1,0) [0|255] ""  SBMU
 SG_ M2S_CMD2_CUS_Reserve4_14 : 24|8@1+ (1,0) [0|255] ""  SBMU
 SG_ M2S_CMD2_CUS_Reserve5_14 : 32|8@1+ (1,0) [0|255] ""  SBMU
 SG_ M2S_CMD2_CUS_Reserve6_14 : 40|8@1+ (1,0) [0|255] ""  SBMU
 SG_ M2S_CMD2_CUS_Reserve7_14 : 48|8@1+ (1,0) [0|255] ""  SBMU
 SG_ M2S_CMD2_CUS_Reserve8_14 : 56|8@1+ (1,0) [0|255] ""  SBMU

BO_ 2154987423 M2S_CMD2_CUS__15: 8 MBMU
 SG_ M2S_CMD2_CUS_Reserve1_15 : 0|8@1+ (1,0) [0|255] ""  SBMU
 SG_ M2S_CMD2_CUS_Reserve2_15 : 8|8@1+ (1,0) [0|255] ""  SBMU
 SG_ M2S_CMD2_CUS_Reserve3_15 : 16|8@1+ (1,0) [0|255] ""  SBMU
 SG_ M2S_CMD2_CUS_Reserve4_15 : 24|8@1+ (1,0) [0|255] ""  SBMU
 SG_ M2S_CMD2_CUS_Reserve5_15 : 32|8@1+ (1,0) [0|255] ""  SBMU
 SG_ M2S_CMD2_CUS_Reserve6_15 : 40|8@1+ (1,0) [0|255] ""  SBMU
 SG_ M2S_CMD2_CUS_Reserve7_15 : 48|8@1+ (1,0) [0|255] ""  SBMU
 SG_ M2S_CMD2_CUS_Reserve8_15 : 56|8@1+ (1,0) [0|255] ""  SBMU

BO_ 2154987424 M2S_CMD2_CUS__16: 8 MBMU
 SG_ M2S_CMD2_CUS_Reserve1_16 : 0|8@1+ (1,0) [0|255] ""  SBMU
 SG_ M2S_CMD2_CUS_Reserve2_16 : 8|8@1+ (1,0) [0|255] ""  SBMU
 SG_ M2S_CMD2_CUS_Reserve3_16 : 16|8@1+ (1,0) [0|255] ""  SBMU
 SG_ M2S_CMD2_CUS_Reserve4_16 : 24|8@1+ (1,0) [0|255] ""  SBMU
 SG_ M2S_CMD2_CUS_Reserve5_16 : 32|8@1+ (1,0) [0|255] ""  SBMU
 SG_ M2S_CMD2_CUS_Reserve6_16 : 40|8@1+ (1,0) [0|255] ""  SBMU
 SG_ M2S_CMD2_CUS_Reserve7_16 : 48|8@1+ (1,0) [0|255] ""  SBMU
 SG_ M2S_CMD2_CUS_Reserve8_16 : 56|8@1+ (1,0) [0|255] ""  SBMU

BO_ 2154987425 M2S_CMD2_CUS__17: 8 MBMU
 SG_ M2S_CMD2_CUS_Reserve1_17 : 0|8@1+ (1,0) [0|255] ""  SBMU
 SG_ M2S_CMD2_CUS_Reserve2_17 : 8|8@1+ (1,0) [0|255] ""  SBMU
 SG_ M2S_CMD2_CUS_Reserve3_17 : 16|8@1+ (1,0) [0|255] ""  SBMU
 SG_ M2S_CMD2_CUS_Reserve4_17 : 24|8@1+ (1,0) [0|255] ""  SBMU
 SG_ M2S_CMD2_CUS_Reserve5_17 : 32|8@1+ (1,0) [0|255] ""  SBMU
 SG_ M2S_CMD2_CUS_Reserve6_17 : 40|8@1+ (1,0) [0|255] ""  SBMU
 SG_ M2S_CMD2_CUS_Reserve7_17 : 48|8@1+ (1,0) [0|255] ""  SBMU
 SG_ M2S_CMD2_CUS_Reserve8_17 : 56|8@1+ (1,0) [0|255] ""  SBMU

BO_ 2154987426 M2S_CMD2_CUS__18: 8 MBMU
 SG_ M2S_CMD2_CUS_Reserve1_18 : 0|8@1+ (1,0) [0|255] ""  SBMU
 SG_ M2S_CMD2_CUS_Reserve2_18 : 8|8@1+ (1,0) [0|255] ""  SBMU
 SG_ M2S_CMD2_CUS_Reserve3_18 : 16|8@1+ (1,0) [0|255] ""  SBMU
 SG_ M2S_CMD2_CUS_Reserve4_18 : 24|8@1+ (1,0) [0|255] ""  SBMU
 SG_ M2S_CMD2_CUS_Reserve5_18 : 32|8@1+ (1,0) [0|255] ""  SBMU
 SG_ M2S_CMD2_CUS_Reserve6_18 : 40|8@1+ (1,0) [0|255] ""  SBMU
 SG_ M2S_CMD2_CUS_Reserve7_18 : 48|8@1+ (1,0) [0|255] ""  SBMU
 SG_ M2S_CMD2_CUS_Reserve8_18 : 56|8@1+ (1,0) [0|255] ""  SBMU

BO_ 2154987427 M2S_CMD2_CUS__19: 8 MBMU
 SG_ M2S_CMD2_CUS_Reserve1_19 : 0|8@1+ (1,0) [0|255] ""  SBMU
 SG_ M2S_CMD2_CUS_Reserve2_19 : 8|8@1+ (1,0) [0|255] ""  SBMU
 SG_ M2S_CMD2_CUS_Reserve3_19 : 16|8@1+ (1,0) [0|255] ""  SBMU
 SG_ M2S_CMD2_CUS_Reserve4_19 : 24|8@1+ (1,0) [0|255] ""  SBMU
 SG_ M2S_CMD2_CUS_Reserve5_19 : 32|8@1+ (1,0) [0|255] ""  SBMU
 SG_ M2S_CMD2_CUS_Reserve6_19 : 40|8@1+ (1,0) [0|255] ""  SBMU
 SG_ M2S_CMD2_CUS_Reserve7_19 : 48|8@1+ (1,0) [0|255] ""  SBMU
 SG_ M2S_CMD2_CUS_Reserve8_19 : 56|8@1+ (1,0) [0|255] ""  SBMU

BO_ 2154987428 M2S_CMD2_CUS__20: 8 MBMU
 SG_ M2S_CMD2_CUS_Reserve1_20 : 0|8@1+ (1,0) [0|255] ""  SBMU
 SG_ M2S_CMD2_CUS_Reserve2_20 : 8|8@1+ (1,0) [0|255] ""  SBMU
 SG_ M2S_CMD2_CUS_Reserve3_20 : 16|8@1+ (1,0) [0|255] ""  SBMU
 SG_ M2S_CMD2_CUS_Reserve4_20 : 24|8@1+ (1,0) [0|255] ""  SBMU
 SG_ M2S_CMD2_CUS_Reserve5_20 : 32|8@1+ (1,0) [0|255] ""  SBMU
 SG_ M2S_CMD2_CUS_Reserve6_20 : 40|8@1+ (1,0) [0|255] ""  SBMU
 SG_ M2S_CMD2_CUS_Reserve7_20 : 48|8@1+ (1,0) [0|255] ""  SBMU
 SG_ M2S_CMD2_CUS_Reserve8_20 : 56|8@1+ (1,0) [0|255] ""  SBMU

BO_ 2154987429 M2S_CMD2_CUS__21: 8 MBMU
 SG_ M2S_CMD2_CUS_Reserve1_21 : 0|8@1+ (1,0) [0|255] ""  SBMU
 SG_ M2S_CMD2_CUS_Reserve2_21 : 8|8@1+ (1,0) [0|255] ""  SBMU
 SG_ M2S_CMD2_CUS_Reserve3_21 : 16|8@1+ (1,0) [0|255] ""  SBMU
 SG_ M2S_CMD2_CUS_Reserve4_21 : 24|8@1+ (1,0) [0|255] ""  SBMU
 SG_ M2S_CMD2_CUS_Reserve5_21 : 32|8@1+ (1,0) [0|255] ""  SBMU
 SG_ M2S_CMD2_CUS_Reserve6_21 : 40|8@1+ (1,0) [0|255] ""  SBMU
 SG_ M2S_CMD2_CUS_Reserve7_21 : 48|8@1+ (1,0) [0|255] ""  SBMU
 SG_ M2S_CMD2_CUS_Reserve8_21 : 56|8@1+ (1,0) [0|255] ""  SBMU

BO_ 2154987430 M2S_CMD2_CUS__22: 8 MBMU
 SG_ M2S_CMD2_CUS_Reserve1_22 : 0|8@1+ (1,0) [0|255] ""  SBMU
 SG_ M2S_CMD2_CUS_Reserve2_22 : 8|8@1+ (1,0) [0|255] ""  SBMU
 SG_ M2S_CMD2_CUS_Reserve3_22 : 16|8@1+ (1,0) [0|255] ""  SBMU
 SG_ M2S_CMD2_CUS_Reserve4_22 : 24|8@1+ (1,0) [0|255] ""  SBMU
 SG_ M2S_CMD2_CUS_Reserve5_22 : 32|8@1+ (1,0) [0|255] ""  SBMU
 SG_ M2S_CMD2_CUS_Reserve6_22 : 40|8@1+ (1,0) [0|255] ""  SBMU
 SG_ M2S_CMD2_CUS_Reserve7_22 : 48|8@1+ (1,0) [0|255] ""  SBMU
 SG_ M2S_CMD2_CUS_Reserve8_22 : 56|8@1+ (1,0) [0|255] ""  SBMU

BO_ 2154987431 M2S_CMD2_CUS__23: 8 MBMU
 SG_ M2S_CMD2_CUS_Reserve1_23 : 0|8@1+ (1,0) [0|255] ""  SBMU
 SG_ M2S_CMD2_CUS_Reserve2_23 : 8|8@1+ (1,0) [0|255] ""  SBMU
 SG_ M2S_CMD2_CUS_Reserve3_23 : 16|8@1+ (1,0) [0|255] ""  SBMU
 SG_ M2S_CMD2_CUS_Reserve4_23 : 24|8@1+ (1,0) [0|255] ""  SBMU
 SG_ M2S_CMD2_CUS_Reserve5_23 : 32|8@1+ (1,0) [0|255] ""  SBMU
 SG_ M2S_CMD2_CUS_Reserve6_23 : 40|8@1+ (1,0) [0|255] ""  SBMU
 SG_ M2S_CMD2_CUS_Reserve7_23 : 48|8@1+ (1,0) [0|255] ""  SBMU
 SG_ M2S_CMD2_CUS_Reserve8_23 : 56|8@1+ (1,0) [0|255] ""  SBMU

BO_ 2154987432 M2S_CMD2_CUS__24: 8 MBMU
 SG_ M2S_CMD2_CUS_Reserve1_24 : 0|8@1+ (1,0) [0|255] ""  SBMU
 SG_ M2S_CMD2_CUS_Reserve2_24 : 8|8@1+ (1,0) [0|255] ""  SBMU
 SG_ M2S_CMD2_CUS_Reserve3_24 : 16|8@1+ (1,0) [0|255] ""  SBMU
 SG_ M2S_CMD2_CUS_Reserve4_24 : 24|8@1+ (1,0) [0|255] ""  SBMU
 SG_ M2S_CMD2_CUS_Reserve5_24 : 32|8@1+ (1,0) [0|255] ""  SBMU
 SG_ M2S_CMD2_CUS_Reserve6_24 : 40|8@1+ (1,0) [0|255] ""  SBMU
 SG_ M2S_CMD2_CUS_Reserve7_24 : 48|8@1+ (1,0) [0|255] ""  SBMU
 SG_ M2S_CMD2_CUS_Reserve8_24 : 56|8@1+ (1,0) [0|255] ""  SBMU

BO_ 2154987433 M2S_CMD2_CUS__25: 8 MBMU
 SG_ M2S_CMD2_CUS_Reserve1_25 : 0|8@1+ (1,0) [0|255] ""  SBMU
 SG_ M2S_CMD2_CUS_Reserve2_25 : 8|8@1+ (1,0) [0|255] ""  SBMU
 SG_ M2S_CMD2_CUS_Reserve3_25 : 16|8@1+ (1,0) [0|255] ""  SBMU
 SG_ M2S_CMD2_CUS_Reserve4_25 : 24|8@1+ (1,0) [0|255] ""  SBMU
 SG_ M2S_CMD2_CUS_Reserve5_25 : 32|8@1+ (1,0) [0|255] ""  SBMU
 SG_ M2S_CMD2_CUS_Reserve6_25 : 40|8@1+ (1,0) [0|255] ""  SBMU
 SG_ M2S_CMD2_CUS_Reserve7_25 : 48|8@1+ (1,0) [0|255] ""  SBMU
 SG_ M2S_CMD2_CUS_Reserve8_25 : 56|8@1+ (1,0) [0|255] ""  SBMU

BO_ 2154987434 M2S_CMD2_CUS__26: 8 MBMU
 SG_ M2S_CMD2_CUS_Reserve1_26 : 0|8@1+ (1,0) [0|255] ""  SBMU
 SG_ M2S_CMD2_CUS_Reserve2_26 : 8|8@1+ (1,0) [0|255] ""  SBMU
 SG_ M2S_CMD2_CUS_Reserve3_26 : 16|8@1+ (1,0) [0|255] ""  SBMU
 SG_ M2S_CMD2_CUS_Reserve4_26 : 24|8@1+ (1,0) [0|255] ""  SBMU
 SG_ M2S_CMD2_CUS_Reserve5_26 : 32|8@1+ (1,0) [0|255] ""  SBMU
 SG_ M2S_CMD2_CUS_Reserve6_26 : 40|8@1+ (1,0) [0|255] ""  SBMU
 SG_ M2S_CMD2_CUS_Reserve7_26 : 48|8@1+ (1,0) [0|255] ""  SBMU
 SG_ M2S_CMD2_CUS_Reserve8_26 : 56|8@1+ (1,0) [0|255] ""  SBMU

BO_ 2154987435 M2S_CMD2_CUS__27: 8 MBMU
 SG_ M2S_CMD2_CUS_Reserve1_27 : 0|8@1+ (1,0) [0|255] ""  SBMU
 SG_ M2S_CMD2_CUS_Reserve2_27 : 8|8@1+ (1,0) [0|255] ""  SBMU
 SG_ M2S_CMD2_CUS_Reserve3_27 : 16|8@1+ (1,0) [0|255] ""  SBMU
 SG_ M2S_CMD2_CUS_Reserve4_27 : 24|8@1+ (1,0) [0|255] ""  SBMU
 SG_ M2S_CMD2_CUS_Reserve5_27 : 32|8@1+ (1,0) [0|255] ""  SBMU
 SG_ M2S_CMD2_CUS_Reserve6_27 : 40|8@1+ (1,0) [0|255] ""  SBMU
 SG_ M2S_CMD2_CUS_Reserve7_27 : 48|8@1+ (1,0) [0|255] ""  SBMU
 SG_ M2S_CMD2_CUS_Reserve8_27 : 56|8@1+ (1,0) [0|255] ""  SBMU

BO_ 2154987436 M2S_CMD2_CUS__28: 8 MBMU
 SG_ M2S_CMD2_CUS_Reserve1_28 : 0|8@1+ (1,0) [0|255] ""  SBMU
 SG_ M2S_CMD2_CUS_Reserve2_28 : 8|8@1+ (1,0) [0|255] ""  SBMU
 SG_ M2S_CMD2_CUS_Reserve3_28 : 16|8@1+ (1,0) [0|255] ""  SBMU
 SG_ M2S_CMD2_CUS_Reserve4_28 : 24|8@1+ (1,0) [0|255] ""  SBMU
 SG_ M2S_CMD2_CUS_Reserve5_28 : 32|8@1+ (1,0) [0|255] ""  SBMU
 SG_ M2S_CMD2_CUS_Reserve6_28 : 40|8@1+ (1,0) [0|255] ""  SBMU
 SG_ M2S_CMD2_CUS_Reserve7_28 : 48|8@1+ (1,0) [0|255] ""  SBMU
 SG_ M2S_CMD2_CUS_Reserve8_28 : 56|8@1+ (1,0) [0|255] ""  SBMU

BO_ 2154987437 M2S_CMD2_CUS__29: 8 MBMU
 SG_ M2S_CMD2_CUS_Reserve1_29 : 0|8@1+ (1,0) [0|255] ""  SBMU
 SG_ M2S_CMD2_CUS_Reserve2_29 : 8|8@1+ (1,0) [0|255] ""  SBMU
 SG_ M2S_CMD2_CUS_Reserve3_29 : 16|8@1+ (1,0) [0|255] ""  SBMU
 SG_ M2S_CMD2_CUS_Reserve4_29 : 24|8@1+ (1,0) [0|255] ""  SBMU
 SG_ M2S_CMD2_CUS_Reserve5_29 : 32|8@1+ (1,0) [0|255] ""  SBMU
 SG_ M2S_CMD2_CUS_Reserve6_29 : 40|8@1+ (1,0) [0|255] ""  SBMU
 SG_ M2S_CMD2_CUS_Reserve7_29 : 48|8@1+ (1,0) [0|255] ""  SBMU
 SG_ M2S_CMD2_CUS_Reserve8_29 : 56|8@1+ (1,0) [0|255] ""  SBMU

BO_ 2154987438 M2S_CMD2_CUS__30: 8 MBMU
 SG_ M2S_CMD2_CUS_Reserve1_30 : 0|8@1+ (1,0) [0|255] ""  SBMU
 SG_ M2S_CMD2_CUS_Reserve2_30 : 8|8@1+ (1,0) [0|255] ""  SBMU
 SG_ M2S_CMD2_CUS_Reserve3_30 : 16|8@1+ (1,0) [0|255] ""  SBMU
 SG_ M2S_CMD2_CUS_Reserve4_30 : 24|8@1+ (1,0) [0|255] ""  SBMU
 SG_ M2S_CMD2_CUS_Reserve5_30 : 32|8@1+ (1,0) [0|255] ""  SBMU
 SG_ M2S_CMD2_CUS_Reserve6_30 : 40|8@1+ (1,0) [0|255] ""  SBMU
 SG_ M2S_CMD2_CUS_Reserve7_30 : 48|8@1+ (1,0) [0|255] ""  SBMU
 SG_ M2S_CMD2_CUS_Reserve8_30 : 56|8@1+ (1,0) [0|255] ""  SBMU

BO_ 2154987439 M2S_CMD2_CUS__31: 8 MBMU
 SG_ M2S_CMD2_CUS_Reserve1_31 : 0|8@1+ (1,0) [0|255] ""  SBMU
 SG_ M2S_CMD2_CUS_Reserve2_31 : 8|8@1+ (1,0) [0|255] ""  SBMU
 SG_ M2S_CMD2_CUS_Reserve3_31 : 16|8@1+ (1,0) [0|255] ""  SBMU
 SG_ M2S_CMD2_CUS_Reserve4_31 : 24|8@1+ (1,0) [0|255] ""  SBMU
 SG_ M2S_CMD2_CUS_Reserve5_31 : 32|8@1+ (1,0) [0|255] ""  SBMU
 SG_ M2S_CMD2_CUS_Reserve6_31 : 40|8@1+ (1,0) [0|255] ""  SBMU
 SG_ M2S_CMD2_CUS_Reserve7_31 : 48|8@1+ (1,0) [0|255] ""  SBMU
 SG_ M2S_CMD2_CUS_Reserve8_31 : 56|8@1+ (1,0) [0|255] ""  SBMU

BO_ 2155052945 M2S_CMD3_CUS__01: 8 MBMU
 SG_ M2S_CMD3_CUS_Reserve1_01 : 0|8@1+ (1,0) [0|255] ""  SBMU
 SG_ M2S_CMD3_CUS_Reserve2_01 : 8|8@1+ (1,0) [0|255] ""  SBMU
 SG_ M2S_CMD3_CUS_Reserve3_01 : 16|8@1+ (1,0) [0|255] ""  SBMU
 SG_ M2S_CMD3_CUS_Reserve4_01 : 24|8@1+ (1,0) [0|255] ""  SBMU
 SG_ M2S_CMD3_CUS_Reserve5_01 : 32|8@1+ (1,0) [0|255] ""  SBMU
 SG_ M2S_CMD3_CUS_Reserve6_01 : 40|8@1+ (1,0) [0|255] ""  SBMU
 SG_ M2S_CMD3_CUS_Reserve7_01 : 48|8@1+ (1,0) [0|255] ""  SBMU
 SG_ M2S_CMD3_CUS_Reserve8_01 : 56|8@1+ (1,0) [0|255] ""  SBMU

BO_ 2155052946 M2S_CMD3_CUS__02: 8 MBMU
 SG_ M2S_CMD3_CUS_Reserve1_02 : 0|8@1+ (1,0) [0|255] ""  SBMU
 SG_ M2S_CMD3_CUS_Reserve2_02 : 8|8@1+ (1,0) [0|255] ""  SBMU
 SG_ M2S_CMD3_CUS_Reserve3_02 : 16|8@1+ (1,0) [0|255] ""  SBMU
 SG_ M2S_CMD3_CUS_Reserve4_02 : 24|8@1+ (1,0) [0|255] ""  SBMU
 SG_ M2S_CMD3_CUS_Reserve5_02 : 32|8@1+ (1,0) [0|255] ""  SBMU
 SG_ M2S_CMD3_CUS_Reserve6_02 : 40|8@1+ (1,0) [0|255] ""  SBMU
 SG_ M2S_CMD3_CUS_Reserve7_02 : 48|8@1+ (1,0) [0|255] ""  SBMU
 SG_ M2S_CMD3_CUS_Reserve8_02 : 56|8@1+ (1,0) [0|255] ""  SBMU

BO_ 2155052947 M2S_CMD3_CUS__03: 8 MBMU
 SG_ M2S_CMD3_CUS_Reserve1_03 : 0|8@1+ (1,0) [0|255] ""  SBMU
 SG_ M2S_CMD3_CUS_Reserve2_03 : 8|8@1+ (1,0) [0|255] ""  SBMU
 SG_ M2S_CMD3_CUS_Reserve3_03 : 16|8@1+ (1,0) [0|255] ""  SBMU
 SG_ M2S_CMD3_CUS_Reserve4_03 : 24|8@1+ (1,0) [0|255] ""  SBMU
 SG_ M2S_CMD3_CUS_Reserve5_03 : 32|8@1+ (1,0) [0|255] ""  SBMU
 SG_ M2S_CMD3_CUS_Reserve6_03 : 40|8@1+ (1,0) [0|255] ""  SBMU
 SG_ M2S_CMD3_CUS_Reserve7_03 : 48|8@1+ (1,0) [0|255] ""  SBMU
 SG_ M2S_CMD3_CUS_Reserve8_03 : 56|8@1+ (1,0) [0|255] ""  SBMU

BO_ 2155052948 M2S_CMD3_CUS__04: 8 MBMU
 SG_ M2S_CMD3_CUS_Reserve1_04 : 0|8@1+ (1,0) [0|255] ""  SBMU
 SG_ M2S_CMD3_CUS_Reserve2_04 : 8|8@1+ (1,0) [0|255] ""  SBMU
 SG_ M2S_CMD3_CUS_Reserve3_04 : 16|8@1+ (1,0) [0|255] ""  SBMU
 SG_ M2S_CMD3_CUS_Reserve4_04 : 24|8@1+ (1,0) [0|255] ""  SBMU
 SG_ M2S_CMD3_CUS_Reserve5_04 : 32|8@1+ (1,0) [0|255] ""  SBMU
 SG_ M2S_CMD3_CUS_Reserve6_04 : 40|8@1+ (1,0) [0|255] ""  SBMU
 SG_ M2S_CMD3_CUS_Reserve7_04 : 48|8@1+ (1,0) [0|255] ""  SBMU
 SG_ M2S_CMD3_CUS_Reserve8_04 : 56|8@1+ (1,0) [0|255] ""  SBMU

BO_ 2155052949 M2S_CMD3_CUS__05: 8 MBMU
 SG_ M2S_CMD3_CUS_Reserve1_05 : 0|8@1+ (1,0) [0|255] ""  SBMU
 SG_ M2S_CMD3_CUS_Reserve2_05 : 8|8@1+ (1,0) [0|255] ""  SBMU
 SG_ M2S_CMD3_CUS_Reserve3_05 : 16|8@1+ (1,0) [0|255] ""  SBMU
 SG_ M2S_CMD3_CUS_Reserve4_05 : 24|8@1+ (1,0) [0|255] ""  SBMU
 SG_ M2S_CMD3_CUS_Reserve5_05 : 32|8@1+ (1,0) [0|255] ""  SBMU
 SG_ M2S_CMD3_CUS_Reserve6_05 : 40|8@1+ (1,0) [0|255] ""  SBMU
 SG_ M2S_CMD3_CUS_Reserve7_05 : 48|8@1+ (1,0) [0|255] ""  SBMU
 SG_ M2S_CMD3_CUS_Reserve8_05 : 56|8@1+ (1,0) [0|255] ""  SBMU

BO_ 2155052950 M2S_CMD3_CUS__06: 8 MBMU
 SG_ M2S_CMD3_CUS_Reserve1_06 : 0|8@1+ (1,0) [0|255] ""  SBMU
 SG_ M2S_CMD3_CUS_Reserve2_06 : 8|8@1+ (1,0) [0|255] ""  SBMU
 SG_ M2S_CMD3_CUS_Reserve3_06 : 16|8@1+ (1,0) [0|255] ""  SBMU
 SG_ M2S_CMD3_CUS_Reserve4_06 : 24|8@1+ (1,0) [0|255] ""  SBMU
 SG_ M2S_CMD3_CUS_Reserve5_06 : 32|8@1+ (1,0) [0|255] ""  SBMU
 SG_ M2S_CMD3_CUS_Reserve6_06 : 40|8@1+ (1,0) [0|255] ""  SBMU
 SG_ M2S_CMD3_CUS_Reserve7_06 : 48|8@1+ (1,0) [0|255] ""  SBMU
 SG_ M2S_CMD3_CUS_Reserve8_06 : 56|8@1+ (1,0) [0|255] ""  SBMU

BO_ 2155052951 M2S_CMD3_CUS__07: 8 MBMU
 SG_ M2S_CMD3_CUS_Reserve1_07 : 0|8@1+ (1,0) [0|255] ""  SBMU
 SG_ M2S_CMD3_CUS_Reserve2_07 : 8|8@1+ (1,0) [0|255] ""  SBMU
 SG_ M2S_CMD3_CUS_Reserve3_07 : 16|8@1+ (1,0) [0|255] ""  SBMU
 SG_ M2S_CMD3_CUS_Reserve4_07 : 24|8@1+ (1,0) [0|255] ""  SBMU
 SG_ M2S_CMD3_CUS_Reserve5_07 : 32|8@1+ (1,0) [0|255] ""  SBMU
 SG_ M2S_CMD3_CUS_Reserve6_07 : 40|8@1+ (1,0) [0|255] ""  SBMU
 SG_ M2S_CMD3_CUS_Reserve7_07 : 48|8@1+ (1,0) [0|255] ""  SBMU
 SG_ M2S_CMD3_CUS_Reserve8_07 : 56|8@1+ (1,0) [0|255] ""  SBMU

BO_ 2155052952 M2S_CMD3_CUS__08: 8 MBMU
 SG_ M2S_CMD3_CUS_Reserve1_08 : 0|8@1+ (1,0) [0|255] ""  SBMU
 SG_ M2S_CMD3_CUS_Reserve2_08 : 8|8@1+ (1,0) [0|255] ""  SBMU
 SG_ M2S_CMD3_CUS_Reserve3_08 : 16|8@1+ (1,0) [0|255] ""  SBMU
 SG_ M2S_CMD3_CUS_Reserve4_08 : 24|8@1+ (1,0) [0|255] ""  SBMU
 SG_ M2S_CMD3_CUS_Reserve5_08 : 32|8@1+ (1,0) [0|255] ""  SBMU
 SG_ M2S_CMD3_CUS_Reserve6_08 : 40|8@1+ (1,0) [0|255] ""  SBMU
 SG_ M2S_CMD3_CUS_Reserve7_08 : 48|8@1+ (1,0) [0|255] ""  SBMU
 SG_ M2S_CMD3_CUS_Reserve8_08 : 56|8@1+ (1,0) [0|255] ""  SBMU

BO_ 2155052953 M2S_CMD3_CUS__09: 8 MBMU
 SG_ M2S_CMD3_CUS_Reserve1_09 : 0|8@1+ (1,0) [0|255] ""  SBMU
 SG_ M2S_CMD3_CUS_Reserve2_09 : 8|8@1+ (1,0) [0|255] ""  SBMU
 SG_ M2S_CMD3_CUS_Reserve3_09 : 16|8@1+ (1,0) [0|255] ""  SBMU
 SG_ M2S_CMD3_CUS_Reserve4_09 : 24|8@1+ (1,0) [0|255] ""  SBMU
 SG_ M2S_CMD3_CUS_Reserve5_09 : 32|8@1+ (1,0) [0|255] ""  SBMU
 SG_ M2S_CMD3_CUS_Reserve6_09 : 40|8@1+ (1,0) [0|255] ""  SBMU
 SG_ M2S_CMD3_CUS_Reserve7_09 : 48|8@1+ (1,0) [0|255] ""  SBMU
 SG_ M2S_CMD3_CUS_Reserve8_09 : 56|8@1+ (1,0) [0|255] ""  SBMU

BO_ 2155052954 M2S_CMD3_CUS__10: 8 MBMU
 SG_ M2S_CMD3_CUS_Reserve1_10 : 0|8@1+ (1,0) [0|255] ""  SBMU
 SG_ M2S_CMD3_CUS_Reserve2_10 : 8|8@1+ (1,0) [0|255] ""  SBMU
 SG_ M2S_CMD3_CUS_Reserve3_10 : 16|8@1+ (1,0) [0|255] ""  SBMU
 SG_ M2S_CMD3_CUS_Reserve4_10 : 24|8@1+ (1,0) [0|255] ""  SBMU
 SG_ M2S_CMD3_CUS_Reserve5_10 : 32|8@1+ (1,0) [0|255] ""  SBMU
 SG_ M2S_CMD3_CUS_Reserve6_10 : 40|8@1+ (1,0) [0|255] ""  SBMU
 SG_ M2S_CMD3_CUS_Reserve7_10 : 48|8@1+ (1,0) [0|255] ""  SBMU
 SG_ M2S_CMD3_CUS_Reserve8_10 : 56|8@1+ (1,0) [0|255] ""  SBMU

BO_ 2155052955 M2S_CMD3_CUS__11: 8 MBMU
 SG_ M2S_CMD3_CUS_Reserve1_11 : 0|8@1+ (1,0) [0|255] ""  SBMU
 SG_ M2S_CMD3_CUS_Reserve2_11 : 8|8@1+ (1,0) [0|255] ""  SBMU
 SG_ M2S_CMD3_CUS_Reserve3_11 : 16|8@1+ (1,0) [0|255] ""  SBMU
 SG_ M2S_CMD3_CUS_Reserve4_11 : 24|8@1+ (1,0) [0|255] ""  SBMU
 SG_ M2S_CMD3_CUS_Reserve5_11 : 32|8@1+ (1,0) [0|255] ""  SBMU
 SG_ M2S_CMD3_CUS_Reserve6_11 : 40|8@1+ (1,0) [0|255] ""  SBMU
 SG_ M2S_CMD3_CUS_Reserve7_11 : 48|8@1+ (1,0) [0|255] ""  SBMU
 SG_ M2S_CMD3_CUS_Reserve8_11 : 56|8@1+ (1,0) [0|255] ""  SBMU

BO_ 2155052956 M2S_CMD3_CUS__12: 8 MBMU
 SG_ M2S_CMD3_CUS_Reserve1_12 : 0|8@1+ (1,0) [0|255] ""  SBMU
 SG_ M2S_CMD3_CUS_Reserve2_12 : 8|8@1+ (1,0) [0|255] ""  SBMU
 SG_ M2S_CMD3_CUS_Reserve3_12 : 16|8@1+ (1,0) [0|255] ""  SBMU
 SG_ M2S_CMD3_CUS_Reserve4_12 : 24|8@1+ (1,0) [0|255] ""  SBMU
 SG_ M2S_CMD3_CUS_Reserve5_12 : 32|8@1+ (1,0) [0|255] ""  SBMU
 SG_ M2S_CMD3_CUS_Reserve6_12 : 40|8@1+ (1,0) [0|255] ""  SBMU
 SG_ M2S_CMD3_CUS_Reserve7_12 : 48|8@1+ (1,0) [0|255] ""  SBMU
 SG_ M2S_CMD3_CUS_Reserve8_12 : 56|8@1+ (1,0) [0|255] ""  SBMU

BO_ 2155052957 M2S_CMD3_CUS__13: 8 MBMU
 SG_ M2S_CMD3_CUS_Reserve1_13 : 0|8@1+ (1,0) [0|255] ""  SBMU
 SG_ M2S_CMD3_CUS_Reserve2_13 : 8|8@1+ (1,0) [0|255] ""  SBMU
 SG_ M2S_CMD3_CUS_Reserve3_13 : 16|8@1+ (1,0) [0|255] ""  SBMU
 SG_ M2S_CMD3_CUS_Reserve4_13 : 24|8@1+ (1,0) [0|255] ""  SBMU
 SG_ M2S_CMD3_CUS_Reserve5_13 : 32|8@1+ (1,0) [0|255] ""  SBMU
 SG_ M2S_CMD3_CUS_Reserve6_13 : 40|8@1+ (1,0) [0|255] ""  SBMU
 SG_ M2S_CMD3_CUS_Reserve7_13 : 48|8@1+ (1,0) [0|255] ""  SBMU
 SG_ M2S_CMD3_CUS_Reserve8_13 : 56|8@1+ (1,0) [0|255] ""  SBMU

BO_ 2155052958 M2S_CMD3_CUS__14: 8 MBMU
 SG_ M2S_CMD3_CUS_Reserve1_14 : 0|8@1+ (1,0) [0|255] ""  SBMU
 SG_ M2S_CMD3_CUS_Reserve2_14 : 8|8@1+ (1,0) [0|255] ""  SBMU
 SG_ M2S_CMD3_CUS_Reserve3_14 : 16|8@1+ (1,0) [0|255] ""  SBMU
 SG_ M2S_CMD3_CUS_Reserve4_14 : 24|8@1+ (1,0) [0|255] ""  SBMU
 SG_ M2S_CMD3_CUS_Reserve5_14 : 32|8@1+ (1,0) [0|255] ""  SBMU
 SG_ M2S_CMD3_CUS_Reserve6_14 : 40|8@1+ (1,0) [0|255] ""  SBMU
 SG_ M2S_CMD3_CUS_Reserve7_14 : 48|8@1+ (1,0) [0|255] ""  SBMU
 SG_ M2S_CMD3_CUS_Reserve8_14 : 56|8@1+ (1,0) [0|255] ""  SBMU

BO_ 2155052959 M2S_CMD3_CUS__15: 8 MBMU
 SG_ M2S_CMD3_CUS_Reserve1_15 : 0|8@1+ (1,0) [0|255] ""  SBMU
 SG_ M2S_CMD3_CUS_Reserve2_15 : 8|8@1+ (1,0) [0|255] ""  SBMU
 SG_ M2S_CMD3_CUS_Reserve3_15 : 16|8@1+ (1,0) [0|255] ""  SBMU
 SG_ M2S_CMD3_CUS_Reserve4_15 : 24|8@1+ (1,0) [0|255] ""  SBMU
 SG_ M2S_CMD3_CUS_Reserve5_15 : 32|8@1+ (1,0) [0|255] ""  SBMU
 SG_ M2S_CMD3_CUS_Reserve6_15 : 40|8@1+ (1,0) [0|255] ""  SBMU
 SG_ M2S_CMD3_CUS_Reserve7_15 : 48|8@1+ (1,0) [0|255] ""  SBMU
 SG_ M2S_CMD3_CUS_Reserve8_15 : 56|8@1+ (1,0) [0|255] ""  SBMU

BO_ 2155052960 M2S_CMD3_CUS__16: 8 MBMU
 SG_ M2S_CMD3_CUS_Reserve1_16 : 0|8@1+ (1,0) [0|255] ""  SBMU
 SG_ M2S_CMD3_CUS_Reserve2_16 : 8|8@1+ (1,0) [0|255] ""  SBMU
 SG_ M2S_CMD3_CUS_Reserve3_16 : 16|8@1+ (1,0) [0|255] ""  SBMU
 SG_ M2S_CMD3_CUS_Reserve4_16 : 24|8@1+ (1,0) [0|255] ""  SBMU
 SG_ M2S_CMD3_CUS_Reserve5_16 : 32|8@1+ (1,0) [0|255] ""  SBMU
 SG_ M2S_CMD3_CUS_Reserve6_16 : 40|8@1+ (1,0) [0|255] ""  SBMU
 SG_ M2S_CMD3_CUS_Reserve7_16 : 48|8@1+ (1,0) [0|255] ""  SBMU
 SG_ M2S_CMD3_CUS_Reserve8_16 : 56|8@1+ (1,0) [0|255] ""  SBMU

BO_ 2155052961 M2S_CMD3_CUS__17: 8 MBMU
 SG_ M2S_CMD3_CUS_Reserve1_17 : 0|8@1+ (1,0) [0|255] ""  SBMU
 SG_ M2S_CMD3_CUS_Reserve2_17 : 8|8@1+ (1,0) [0|255] ""  SBMU
 SG_ M2S_CMD3_CUS_Reserve3_17 : 16|8@1+ (1,0) [0|255] ""  SBMU
 SG_ M2S_CMD3_CUS_Reserve4_17 : 24|8@1+ (1,0) [0|255] ""  SBMU
 SG_ M2S_CMD3_CUS_Reserve5_17 : 32|8@1+ (1,0) [0|255] ""  SBMU
 SG_ M2S_CMD3_CUS_Reserve6_17 : 40|8@1+ (1,0) [0|255] ""  SBMU
 SG_ M2S_CMD3_CUS_Reserve7_17 : 48|8@1+ (1,0) [0|255] ""  SBMU
 SG_ M2S_CMD3_CUS_Reserve8_17 : 56|8@1+ (1,0) [0|255] ""  SBMU

BO_ 2155052962 M2S_CMD3_CUS__18: 8 MBMU
 SG_ M2S_CMD3_CUS_Reserve1_18 : 0|8@1+ (1,0) [0|255] ""  SBMU
 SG_ M2S_CMD3_CUS_Reserve2_18 : 8|8@1+ (1,0) [0|255] ""  SBMU
 SG_ M2S_CMD3_CUS_Reserve3_18 : 16|8@1+ (1,0) [0|255] ""  SBMU
 SG_ M2S_CMD3_CUS_Reserve4_18 : 24|8@1+ (1,0) [0|255] ""  SBMU
 SG_ M2S_CMD3_CUS_Reserve5_18 : 32|8@1+ (1,0) [0|255] ""  SBMU
 SG_ M2S_CMD3_CUS_Reserve6_18 : 40|8@1+ (1,0) [0|255] ""  SBMU
 SG_ M2S_CMD3_CUS_Reserve7_18 : 48|8@1+ (1,0) [0|255] ""  SBMU
 SG_ M2S_CMD3_CUS_Reserve8_18 : 56|8@1+ (1,0) [0|255] ""  SBMU

BO_ 2155052963 M2S_CMD3_CUS__19: 8 MBMU
 SG_ M2S_CMD3_CUS_Reserve1_19 : 0|8@1+ (1,0) [0|255] ""  SBMU
 SG_ M2S_CMD3_CUS_Reserve2_19 : 8|8@1+ (1,0) [0|255] ""  SBMU
 SG_ M2S_CMD3_CUS_Reserve3_19 : 16|8@1+ (1,0) [0|255] ""  SBMU
 SG_ M2S_CMD3_CUS_Reserve4_19 : 24|8@1+ (1,0) [0|255] ""  SBMU
 SG_ M2S_CMD3_CUS_Reserve5_19 : 32|8@1+ (1,0) [0|255] ""  SBMU
 SG_ M2S_CMD3_CUS_Reserve6_19 : 40|8@1+ (1,0) [0|255] ""  SBMU
 SG_ M2S_CMD3_CUS_Reserve7_19 : 48|8@1+ (1,0) [0|255] ""  SBMU
 SG_ M2S_CMD3_CUS_Reserve8_19 : 56|8@1+ (1,0) [0|255] ""  SBMU

BO_ 2155052964 M2S_CMD3_CUS__20: 8 MBMU
 SG_ M2S_CMD3_CUS_Reserve1_20 : 0|8@1+ (1,0) [0|255] ""  SBMU
 SG_ M2S_CMD3_CUS_Reserve2_20 : 8|8@1+ (1,0) [0|255] ""  SBMU
 SG_ M2S_CMD3_CUS_Reserve3_20 : 16|8@1+ (1,0) [0|255] ""  SBMU
 SG_ M2S_CMD3_CUS_Reserve4_20 : 24|8@1+ (1,0) [0|255] ""  SBMU
 SG_ M2S_CMD3_CUS_Reserve5_20 : 32|8@1+ (1,0) [0|255] ""  SBMU
 SG_ M2S_CMD3_CUS_Reserve6_20 : 40|8@1+ (1,0) [0|255] ""  SBMU
 SG_ M2S_CMD3_CUS_Reserve7_20 : 48|8@1+ (1,0) [0|255] ""  SBMU
 SG_ M2S_CMD3_CUS_Reserve8_20 : 56|8@1+ (1,0) [0|255] ""  SBMU

BO_ 2155052965 M2S_CMD3_CUS__21: 8 MBMU
 SG_ M2S_CMD3_CUS_Reserve1_21 : 0|8@1+ (1,0) [0|255] ""  SBMU
 SG_ M2S_CMD3_CUS_Reserve2_21 : 8|8@1+ (1,0) [0|255] ""  SBMU
 SG_ M2S_CMD3_CUS_Reserve3_21 : 16|8@1+ (1,0) [0|255] ""  SBMU
 SG_ M2S_CMD3_CUS_Reserve4_21 : 24|8@1+ (1,0) [0|255] ""  SBMU
 SG_ M2S_CMD3_CUS_Reserve5_21 : 32|8@1+ (1,0) [0|255] ""  SBMU
 SG_ M2S_CMD3_CUS_Reserve6_21 : 40|8@1+ (1,0) [0|255] ""  SBMU
 SG_ M2S_CMD3_CUS_Reserve7_21 : 48|8@1+ (1,0) [0|255] ""  SBMU
 SG_ M2S_CMD3_CUS_Reserve8_21 : 56|8@1+ (1,0) [0|255] ""  SBMU

BO_ 2155052966 M2S_CMD3_CUS__22: 8 MBMU
 SG_ M2S_CMD3_CUS_Reserve1_22 : 0|8@1+ (1,0) [0|255] ""  SBMU
 SG_ M2S_CMD3_CUS_Reserve2_22 : 8|8@1+ (1,0) [0|255] ""  SBMU
 SG_ M2S_CMD3_CUS_Reserve3_22 : 16|8@1+ (1,0) [0|255] ""  SBMU
 SG_ M2S_CMD3_CUS_Reserve4_22 : 24|8@1+ (1,0) [0|255] ""  SBMU
 SG_ M2S_CMD3_CUS_Reserve5_22 : 32|8@1+ (1,0) [0|255] ""  SBMU
 SG_ M2S_CMD3_CUS_Reserve6_22 : 40|8@1+ (1,0) [0|255] ""  SBMU
 SG_ M2S_CMD3_CUS_Reserve7_22 : 48|8@1+ (1,0) [0|255] ""  SBMU
 SG_ M2S_CMD3_CUS_Reserve8_22 : 56|8@1+ (1,0) [0|255] ""  SBMU

BO_ 2155052967 M2S_CMD3_CUS__23: 8 MBMU
 SG_ M2S_CMD3_CUS_Reserve1_23 : 0|8@1+ (1,0) [0|255] ""  SBMU
 SG_ M2S_CMD3_CUS_Reserve2_23 : 8|8@1+ (1,0) [0|255] ""  SBMU
 SG_ M2S_CMD3_CUS_Reserve3_23 : 16|8@1+ (1,0) [0|255] ""  SBMU
 SG_ M2S_CMD3_CUS_Reserve4_23 : 24|8@1+ (1,0) [0|255] ""  SBMU
 SG_ M2S_CMD3_CUS_Reserve5_23 : 32|8@1+ (1,0) [0|255] ""  SBMU
 SG_ M2S_CMD3_CUS_Reserve6_23 : 40|8@1+ (1,0) [0|255] ""  SBMU
 SG_ M2S_CMD3_CUS_Reserve7_23 : 48|8@1+ (1,0) [0|255] ""  SBMU
 SG_ M2S_CMD3_CUS_Reserve8_23 : 56|8@1+ (1,0) [0|255] ""  SBMU

BO_ 2155052968 M2S_CMD3_CUS__24: 8 MBMU
 SG_ M2S_CMD3_CUS_Reserve1_24 : 0|8@1+ (1,0) [0|255] ""  SBMU
 SG_ M2S_CMD3_CUS_Reserve2_24 : 8|8@1+ (1,0) [0|255] ""  SBMU
 SG_ M2S_CMD3_CUS_Reserve3_24 : 16|8@1+ (1,0) [0|255] ""  SBMU
 SG_ M2S_CMD3_CUS_Reserve4_24 : 24|8@1+ (1,0) [0|255] ""  SBMU
 SG_ M2S_CMD3_CUS_Reserve5_24 : 32|8@1+ (1,0) [0|255] ""  SBMU
 SG_ M2S_CMD3_CUS_Reserve6_24 : 40|8@1+ (1,0) [0|255] ""  SBMU
 SG_ M2S_CMD3_CUS_Reserve7_24 : 48|8@1+ (1,0) [0|255] ""  SBMU
 SG_ M2S_CMD3_CUS_Reserve8_24 : 56|8@1+ (1,0) [0|255] ""  SBMU

BO_ 2155052969 M2S_CMD3_CUS__25: 8 MBMU
 SG_ M2S_CMD3_CUS_Reserve1_25 : 0|8@1+ (1,0) [0|255] ""  SBMU
 SG_ M2S_CMD3_CUS_Reserve2_25 : 8|8@1+ (1,0) [0|255] ""  SBMU
 SG_ M2S_CMD3_CUS_Reserve3_25 : 16|8@1+ (1,0) [0|255] ""  SBMU
 SG_ M2S_CMD3_CUS_Reserve4_25 : 24|8@1+ (1,0) [0|255] ""  SBMU
 SG_ M2S_CMD3_CUS_Reserve5_25 : 32|8@1+ (1,0) [0|255] ""  SBMU
 SG_ M2S_CMD3_CUS_Reserve6_25 : 40|8@1+ (1,0) [0|255] ""  SBMU
 SG_ M2S_CMD3_CUS_Reserve7_25 : 48|8@1+ (1,0) [0|255] ""  SBMU
 SG_ M2S_CMD3_CUS_Reserve8_25 : 56|8@1+ (1,0) [0|255] ""  SBMU

BO_ 2155052970 M2S_CMD3_CUS__26: 8 MBMU
 SG_ M2S_CMD3_CUS_Reserve1_26 : 0|8@1+ (1,0) [0|255] ""  SBMU
 SG_ M2S_CMD3_CUS_Reserve2_26 : 8|8@1+ (1,0) [0|255] ""  SBMU
 SG_ M2S_CMD3_CUS_Reserve3_26 : 16|8@1+ (1,0) [0|255] ""  SBMU
 SG_ M2S_CMD3_CUS_Reserve4_26 : 24|8@1+ (1,0) [0|255] ""  SBMU
 SG_ M2S_CMD3_CUS_Reserve5_26 : 32|8@1+ (1,0) [0|255] ""  SBMU
 SG_ M2S_CMD3_CUS_Reserve6_26 : 40|8@1+ (1,0) [0|255] ""  SBMU
 SG_ M2S_CMD3_CUS_Reserve7_26 : 48|8@1+ (1,0) [0|255] ""  SBMU
 SG_ M2S_CMD3_CUS_Reserve8_26 : 56|8@1+ (1,0) [0|255] ""  SBMU

BO_ 2155052971 M2S_CMD3_CUS__27: 8 MBMU
 SG_ M2S_CMD3_CUS_Reserve1_27 : 0|8@1+ (1,0) [0|255] ""  SBMU
 SG_ M2S_CMD3_CUS_Reserve2_27 : 8|8@1+ (1,0) [0|255] ""  SBMU
 SG_ M2S_CMD3_CUS_Reserve3_27 : 16|8@1+ (1,0) [0|255] ""  SBMU
 SG_ M2S_CMD3_CUS_Reserve4_27 : 24|8@1+ (1,0) [0|255] ""  SBMU
 SG_ M2S_CMD3_CUS_Reserve5_27 : 32|8@1+ (1,0) [0|255] ""  SBMU
 SG_ M2S_CMD3_CUS_Reserve6_27 : 40|8@1+ (1,0) [0|255] ""  SBMU
 SG_ M2S_CMD3_CUS_Reserve7_27 : 48|8@1+ (1,0) [0|255] ""  SBMU
 SG_ M2S_CMD3_CUS_Reserve8_27 : 56|8@1+ (1,0) [0|255] ""  SBMU

BO_ 2155052972 M2S_CMD3_CUS__28: 8 MBMU
 SG_ M2S_CMD3_CUS_Reserve1_28 : 0|8@1+ (1,0) [0|255] ""  SBMU
 SG_ M2S_CMD3_CUS_Reserve2_28 : 8|8@1+ (1,0) [0|255] ""  SBMU
 SG_ M2S_CMD3_CUS_Reserve3_28 : 16|8@1+ (1,0) [0|255] ""  SBMU
 SG_ M2S_CMD3_CUS_Reserve4_28 : 24|8@1+ (1,0) [0|255] ""  SBMU
 SG_ M2S_CMD3_CUS_Reserve5_28 : 32|8@1+ (1,0) [0|255] ""  SBMU
 SG_ M2S_CMD3_CUS_Reserve6_28 : 40|8@1+ (1,0) [0|255] ""  SBMU
 SG_ M2S_CMD3_CUS_Reserve7_28 : 48|8@1+ (1,0) [0|255] ""  SBMU
 SG_ M2S_CMD3_CUS_Reserve8_28 : 56|8@1+ (1,0) [0|255] ""  SBMU

BO_ 2155052973 M2S_CMD3_CUS__29: 8 MBMU
 SG_ M2S_CMD3_CUS_Reserve1_29 : 0|8@1+ (1,0) [0|255] ""  SBMU
 SG_ M2S_CMD3_CUS_Reserve2_29 : 8|8@1+ (1,0) [0|255] ""  SBMU
 SG_ M2S_CMD3_CUS_Reserve3_29 : 16|8@1+ (1,0) [0|255] ""  SBMU
 SG_ M2S_CMD3_CUS_Reserve4_29 : 24|8@1+ (1,0) [0|255] ""  SBMU
 SG_ M2S_CMD3_CUS_Reserve5_29 : 32|8@1+ (1,0) [0|255] ""  SBMU
 SG_ M2S_CMD3_CUS_Reserve6_29 : 40|8@1+ (1,0) [0|255] ""  SBMU
 SG_ M2S_CMD3_CUS_Reserve7_29 : 48|8@1+ (1,0) [0|255] ""  SBMU
 SG_ M2S_CMD3_CUS_Reserve8_29 : 56|8@1+ (1,0) [0|255] ""  SBMU

BO_ 2155052974 M2S_CMD3_CUS__30: 8 MBMU
 SG_ M2S_CMD3_CUS_Reserve1_30 : 0|8@1+ (1,0) [0|255] ""  SBMU
 SG_ M2S_CMD3_CUS_Reserve2_30 : 8|8@1+ (1,0) [0|255] ""  SBMU
 SG_ M2S_CMD3_CUS_Reserve3_30 : 16|8@1+ (1,0) [0|255] ""  SBMU
 SG_ M2S_CMD3_CUS_Reserve4_30 : 24|8@1+ (1,0) [0|255] ""  SBMU
 SG_ M2S_CMD3_CUS_Reserve5_30 : 32|8@1+ (1,0) [0|255] ""  SBMU
 SG_ M2S_CMD3_CUS_Reserve6_30 : 40|8@1+ (1,0) [0|255] ""  SBMU
 SG_ M2S_CMD3_CUS_Reserve7_30 : 48|8@1+ (1,0) [0|255] ""  SBMU
 SG_ M2S_CMD3_CUS_Reserve8_30 : 56|8@1+ (1,0) [0|255] ""  SBMU

BO_ 2155052975 M2S_CMD3_CUS__31: 8 MBMU
 SG_ M2S_CMD3_CUS_Reserve1_31 : 0|8@1+ (1,0) [0|255] ""  SBMU
 SG_ M2S_CMD3_CUS_Reserve2_31 : 8|8@1+ (1,0) [0|255] ""  SBMU
 SG_ M2S_CMD3_CUS_Reserve3_31 : 16|8@1+ (1,0) [0|255] ""  SBMU
 SG_ M2S_CMD3_CUS_Reserve4_31 : 24|8@1+ (1,0) [0|255] ""  SBMU
 SG_ M2S_CMD3_CUS_Reserve5_31 : 32|8@1+ (1,0) [0|255] ""  SBMU
 SG_ M2S_CMD3_CUS_Reserve6_31 : 40|8@1+ (1,0) [0|255] ""  SBMU
 SG_ M2S_CMD3_CUS_Reserve7_31 : 48|8@1+ (1,0) [0|255] ""  SBMU
 SG_ M2S_CMD3_CUS_Reserve8_31 : 56|8@1+ (1,0) [0|255] ""  SBMU

BO_ 2148827025 M2P_LiquidInfo_1__01: 8 MBMU
 SG_ U2T_BMS_ControlMode_1 : 0|2@1+ (1,0) [0|3] ""  PC
 SG_ T2U_TMS_RunState_1 : 2|2@1+ (1,0) [0|3] ""  PC
 SG_ T2U_TMS_FaultCode_1 : 8|6@1+ (1,0) [0|63] ""  PC
 SG_ T2U_TMS_FaultLevel_1 : 14|2@1+ (1,0) [0|3] ""  PC
 SG_ U2T_BMS_TmptSetPoint_1 : 16|8@1+ (1,-50) [-50|205] "℃"  PC
 SG_ T2U_TMS_OutWaterTemp_1 : 24|8@1+ (1,-50) [-50|205] "℃"  PC
 SG_ T2U_TMS_BackWaterTemp_1 : 32|8@1+ (1,-50) [-50|205] "℃"  PC
 SG_ T2U_TMS_EnvTemp_1 : 40|8@1+ (1,-50) [-50|205] "℃"  PC
 SG_ M2P_TMSCoolingProtectMode_1_01 : 48|2@1+ (1,0) [0|3] ""  PC

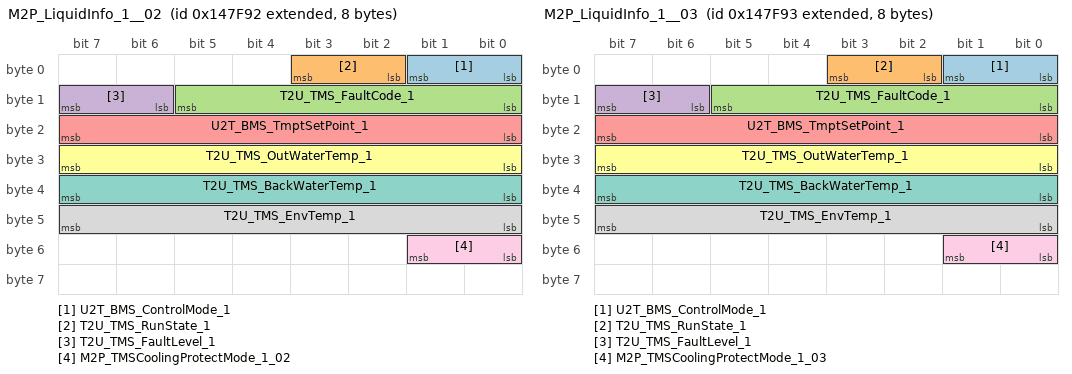
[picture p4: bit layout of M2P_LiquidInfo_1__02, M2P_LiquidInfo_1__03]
BO_ 2148827026 M2P_LiquidInfo_1__02: 8 MBMU
 SG_ U2T_BMS_ControlMode_1 : 0|2@1+ (1,0) [0|3] ""  PC
 SG_ T2U_TMS_RunState_1 : 2|2@1+ (1,0) [0|3] ""  PC
 SG_ T2U_TMS_FaultCode_1 : 8|6@1+ (1,0) [0|63] ""  PC
 SG_ T2U_TMS_FaultLevel_1 : 14|2@1+ (1,0) [0|3] ""  PC
 SG_ U2T_BMS_TmptSetPoint_1 : 16|8@1+ (1,-50) [-50|205] "℃"  PC
 SG_ T2U_TMS_OutWaterTemp_1 : 24|8@1+ (1,-50) [-50|205] "℃"  PC
 SG_ T2U_TMS_BackWaterTemp_1 : 32|8@1+ (1,-50) [-50|205] "℃"  PC
 SG_ T2U_TMS_EnvTemp_1 : 40|8@1+ (1,-50) [-50|205] "℃"  PC
 SG_ M2P_TMSCoolingProtectMode_1_02 : 48|2@1+ (1,0) [0|3] ""  PC

BO_ 2148827027 M2P_LiquidInfo_1__03: 8 MBMU
 SG_ U2T_BMS_ControlMode_1 : 0|2@1+ (1,0) [0|3] ""  PC
 SG_ T2U_TMS_RunState_1 : 2|2@1+ (1,0) [0|3] ""  PC
 SG_ T2U_TMS_FaultCode_1 : 8|6@1+ (1,0) [0|63] ""  PC
 SG_ T2U_TMS_FaultLevel_1 : 14|2@1+ (1,0) [0|3] ""  PC
 SG_ U2T_BMS_TmptSetPoint_1 : 16|8@1+ (1,-50) [-50|205] "℃"  PC
 SG_ T2U_TMS_OutWaterTemp_1 : 24|8@1+ (1,-50) [-50|205] "℃"  PC
 SG_ T2U_TMS_BackWaterTemp_1 : 32|8@1+ (1,-50) [-50|205] "℃"  PC
 SG_ T2U_TMS_EnvTemp_1 : 40|8@1+ (1,-50) [-50|205] "℃"  PC
 SG_ M2P_TMSCoolingProtectMode_1_03 : 48|2@1+ (1,0) [0|3] ""  PC

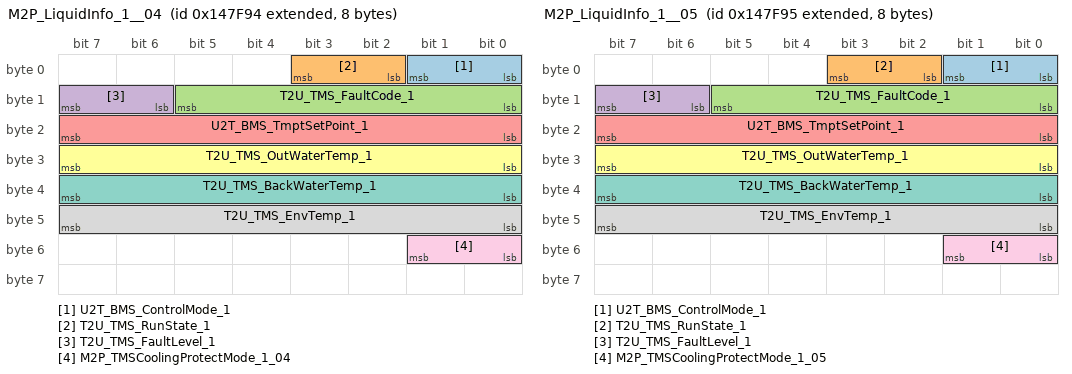
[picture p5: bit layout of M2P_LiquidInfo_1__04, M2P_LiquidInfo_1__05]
BO_ 2148827028 M2P_LiquidInfo_1__04: 8 MBMU
 SG_ U2T_BMS_ControlMode_1 : 0|2@1+ (1,0) [0|3] ""  PC
 SG_ T2U_TMS_RunState_1 : 2|2@1+ (1,0) [0|3] ""  PC
 SG_ T2U_TMS_FaultCode_1 : 8|6@1+ (1,0) [0|63] ""  PC
 SG_ T2U_TMS_FaultLevel_1 : 14|2@1+ (1,0) [0|3] ""  PC
 SG_ U2T_BMS_TmptSetPoint_1 : 16|8@1+ (1,-50) [-50|205] "℃"  PC
 SG_ T2U_TMS_OutWaterTemp_1 : 24|8@1+ (1,-50) [-50|205] "℃"  PC
 SG_ T2U_TMS_BackWaterTemp_1 : 32|8@1+ (1,-50) [-50|205] "℃"  PC
 SG_ T2U_TMS_EnvTemp_1 : 40|8@1+ (1,-50) [-50|205] "℃"  PC
 SG_ M2P_TMSCoolingProtectMode_1_04 : 48|2@1+ (1,0) [0|3] ""  PC

BO_ 2148827029 M2P_LiquidInfo_1__05: 8 MBMU
 SG_ U2T_BMS_ControlMode_1 : 0|2@1+ (1,0) [0|3] ""  PC
 SG_ T2U_TMS_RunState_1 : 2|2@1+ (1,0) [0|3] ""  PC
 SG_ T2U_TMS_FaultCode_1 : 8|6@1+ (1,0) [0|63] ""  PC
 SG_ T2U_TMS_FaultLevel_1 : 14|2@1+ (1,0) [0|3] ""  PC
 SG_ U2T_BMS_TmptSetPoint_1 : 16|8@1+ (1,-50) [-50|205] "℃"  PC
 SG_ T2U_TMS_OutWaterTemp_1 : 24|8@1+ (1,-50) [-50|205] "℃"  PC
 SG_ T2U_TMS_BackWaterTemp_1 : 32|8@1+ (1,-50) [-50|205] "℃"  PC
 SG_ T2U_TMS_EnvTemp_1 : 40|8@1+ (1,-50) [-50|205] "℃"  PC
 SG_ M2P_TMSCoolingProtectMode_1_05 : 48|2@1+ (1,0) [0|3] ""  PC

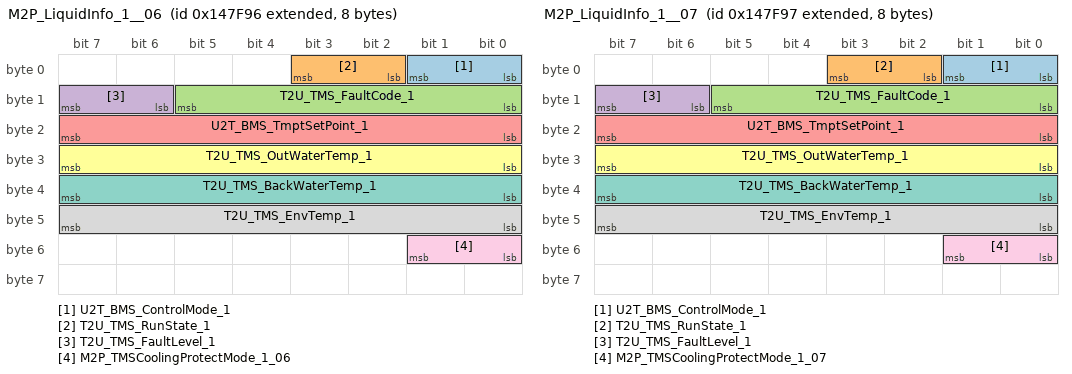
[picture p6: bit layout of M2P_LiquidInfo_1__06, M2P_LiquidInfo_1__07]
BO_ 2148827030 M2P_LiquidInfo_1__06: 8 MBMU
 SG_ U2T_BMS_ControlMode_1 : 0|2@1+ (1,0) [0|3] ""  PC
 SG_ T2U_TMS_RunState_1 : 2|2@1+ (1,0) [0|3] ""  PC
 SG_ T2U_TMS_FaultCode_1 : 8|6@1+ (1,0) [0|63] ""  PC
 SG_ T2U_TMS_FaultLevel_1 : 14|2@1+ (1,0) [0|3] ""  PC
 SG_ U2T_BMS_TmptSetPoint_1 : 16|8@1+ (1,-50) [-50|205] "℃"  PC
 SG_ T2U_TMS_OutWaterTemp_1 : 24|8@1+ (1,-50) [-50|205] "℃"  PC
 SG_ T2U_TMS_BackWaterTemp_1 : 32|8@1+ (1,-50) [-50|205] "℃"  PC
 SG_ T2U_TMS_EnvTemp_1 : 40|8@1+ (1,-50) [-50|205] "℃"  PC
 SG_ M2P_TMSCoolingProtectMode_1_06 : 48|2@1+ (1,0) [0|3] ""  PC

BO_ 2148827031 M2P_LiquidInfo_1__07: 8 MBMU
 SG_ U2T_BMS_ControlMode_1 : 0|2@1+ (1,0) [0|3] ""  PC
 SG_ T2U_TMS_RunState_1 : 2|2@1+ (1,0) [0|3] ""  PC
 SG_ T2U_TMS_FaultCode_1 : 8|6@1+ (1,0) [0|63] ""  PC
 SG_ T2U_TMS_FaultLevel_1 : 14|2@1+ (1,0) [0|3] ""  PC
 SG_ U2T_BMS_TmptSetPoint_1 : 16|8@1+ (1,-50) [-50|205] "℃"  PC
 SG_ T2U_TMS_OutWaterTemp_1 : 24|8@1+ (1,-50) [-50|205] "℃"  PC
 SG_ T2U_TMS_BackWaterTemp_1 : 32|8@1+ (1,-50) [-50|205] "℃"  PC
 SG_ T2U_TMS_EnvTemp_1 : 40|8@1+ (1,-50) [-50|205] "℃"  PC
 SG_ M2P_TMSCoolingProtectMode_1_07 : 48|2@1+ (1,0) [0|3] ""  PC

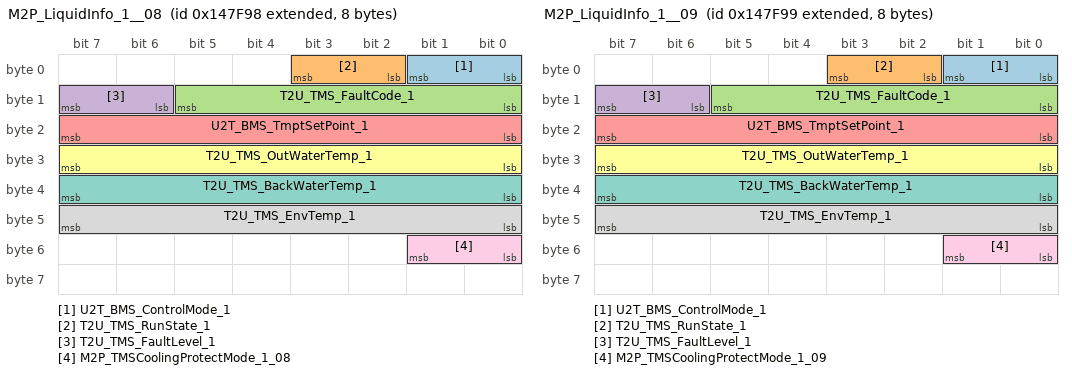
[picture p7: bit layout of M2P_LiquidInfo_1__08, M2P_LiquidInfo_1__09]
BO_ 2148827032 M2P_LiquidInfo_1__08: 8 MBMU
 SG_ U2T_BMS_ControlMode_1 : 0|2@1+ (1,0) [0|3] ""  PC
 SG_ T2U_TMS_RunState_1 : 2|2@1+ (1,0) [0|3] ""  PC
 SG_ T2U_TMS_FaultCode_1 : 8|6@1+ (1,0) [0|63] ""  PC
 SG_ T2U_TMS_FaultLevel_1 : 14|2@1+ (1,0) [0|3] ""  PC
 SG_ U2T_BMS_TmptSetPoint_1 : 16|8@1+ (1,-50) [-50|205] "℃"  PC
 SG_ T2U_TMS_OutWaterTemp_1 : 24|8@1+ (1,-50) [-50|205] "℃"  PC
 SG_ T2U_TMS_BackWaterTemp_1 : 32|8@1+ (1,-50) [-50|205] "℃"  PC
 SG_ T2U_TMS_EnvTemp_1 : 40|8@1+ (1,-50) [-50|205] "℃"  PC
 SG_ M2P_TMSCoolingProtectMode_1_08 : 48|2@1+ (1,0) [0|3] ""  PC

BO_ 2148827033 M2P_LiquidInfo_1__09: 8 MBMU
 SG_ U2T_BMS_ControlMode_1 : 0|2@1+ (1,0) [0|3] ""  PC
 SG_ T2U_TMS_RunState_1 : 2|2@1+ (1,0) [0|3] ""  PC
 SG_ T2U_TMS_FaultCode_1 : 8|6@1+ (1,0) [0|63] ""  PC
 SG_ T2U_TMS_FaultLevel_1 : 14|2@1+ (1,0) [0|3] ""  PC
 SG_ U2T_BMS_TmptSetPoint_1 : 16|8@1+ (1,-50) [-50|205] "℃"  PC
 SG_ T2U_TMS_OutWaterTemp_1 : 24|8@1+ (1,-50) [-50|205] "℃"  PC
 SG_ T2U_TMS_BackWaterTemp_1 : 32|8@1+ (1,-50) [-50|205] "℃"  PC
 SG_ T2U_TMS_EnvTemp_1 : 40|8@1+ (1,-50) [-50|205] "℃"  PC
 SG_ M2P_TMSCoolingProtectMode_1_09 : 48|2@1+ (1,0) [0|3] ""  PC

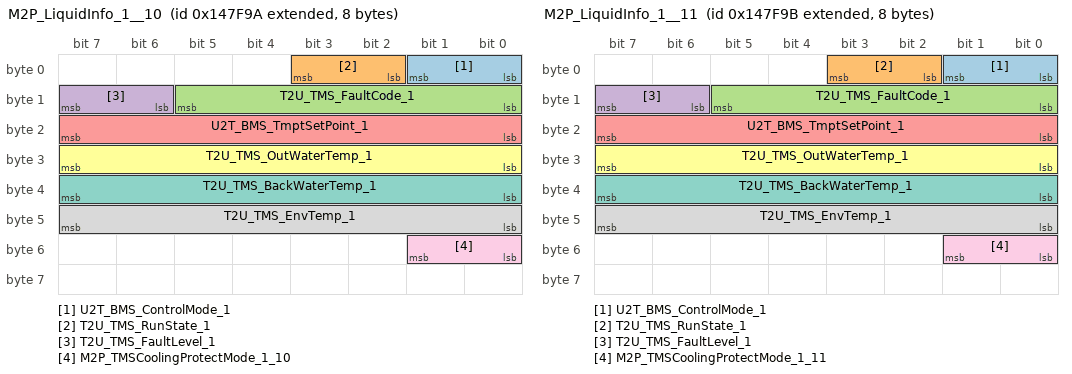
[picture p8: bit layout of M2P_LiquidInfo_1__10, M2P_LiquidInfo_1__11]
BO_ 2148827034 M2P_LiquidInfo_1__10: 8 MBMU
 SG_ U2T_BMS_ControlMode_1 : 0|2@1+ (1,0) [0|3] ""  PC
 SG_ T2U_TMS_RunState_1 : 2|2@1+ (1,0) [0|3] ""  PC
 SG_ T2U_TMS_FaultCode_1 : 8|6@1+ (1,0) [0|63] ""  PC
 SG_ T2U_TMS_FaultLevel_1 : 14|2@1+ (1,0) [0|3] ""  PC
 SG_ U2T_BMS_TmptSetPoint_1 : 16|8@1+ (1,-50) [-50|205] "℃"  PC
 SG_ T2U_TMS_OutWaterTemp_1 : 24|8@1+ (1,-50) [-50|205] "℃"  PC
 SG_ T2U_TMS_BackWaterTemp_1 : 32|8@1+ (1,-50) [-50|205] "℃"  PC
 SG_ T2U_TMS_EnvTemp_1 : 40|8@1+ (1,-50) [-50|205] "℃"  PC
 SG_ M2P_TMSCoolingProtectMode_1_10 : 48|2@1+ (1,0) [0|3] ""  PC

BO_ 2148827035 M2P_LiquidInfo_1__11: 8 MBMU
 SG_ U2T_BMS_ControlMode_1 : 0|2@1+ (1,0) [0|3] ""  PC
 SG_ T2U_TMS_RunState_1 : 2|2@1+ (1,0) [0|3] ""  PC
 SG_ T2U_TMS_FaultCode_1 : 8|6@1+ (1,0) [0|63] ""  PC
 SG_ T2U_TMS_FaultLevel_1 : 14|2@1+ (1,0) [0|3] ""  PC
 SG_ U2T_BMS_TmptSetPoint_1 : 16|8@1+ (1,-50) [-50|205] "℃"  PC
 SG_ T2U_TMS_OutWaterTemp_1 : 24|8@1+ (1,-50) [-50|205] "℃"  PC
 SG_ T2U_TMS_BackWaterTemp_1 : 32|8@1+ (1,-50) [-50|205] "℃"  PC
 SG_ T2U_TMS_EnvTemp_1 : 40|8@1+ (1,-50) [-50|205] "℃"  PC
 SG_ M2P_TMSCoolingProtectMode_1_11 : 48|2@1+ (1,0) [0|3] ""  PC

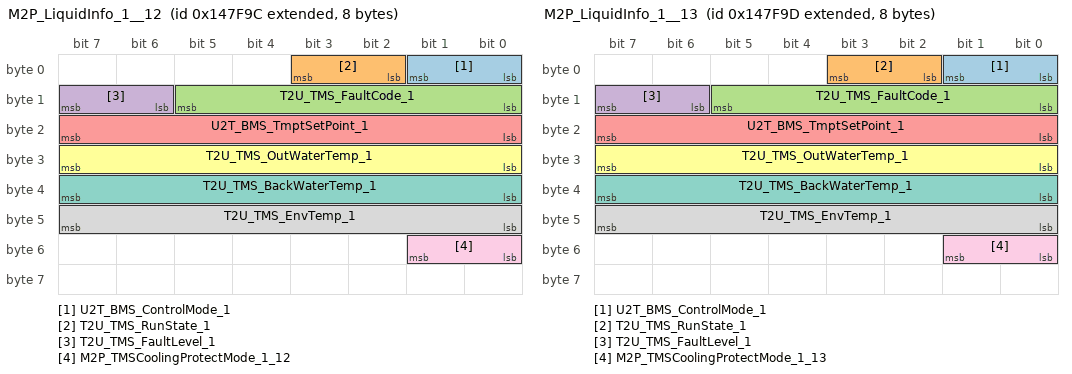
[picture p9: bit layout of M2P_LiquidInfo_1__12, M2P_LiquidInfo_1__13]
BO_ 2148827036 M2P_LiquidInfo_1__12: 8 MBMU
 SG_ U2T_BMS_ControlMode_1 : 0|2@1+ (1,0) [0|3] ""  PC
 SG_ T2U_TMS_RunState_1 : 2|2@1+ (1,0) [0|3] ""  PC
 SG_ T2U_TMS_FaultCode_1 : 8|6@1+ (1,0) [0|63] ""  PC
 SG_ T2U_TMS_FaultLevel_1 : 14|2@1+ (1,0) [0|3] ""  PC
 SG_ U2T_BMS_TmptSetPoint_1 : 16|8@1+ (1,-50) [-50|205] "℃"  PC
 SG_ T2U_TMS_OutWaterTemp_1 : 24|8@1+ (1,-50) [-50|205] "℃"  PC
 SG_ T2U_TMS_BackWaterTemp_1 : 32|8@1+ (1,-50) [-50|205] "℃"  PC
 SG_ T2U_TMS_EnvTemp_1 : 40|8@1+ (1,-50) [-50|205] "℃"  PC
 SG_ M2P_TMSCoolingProtectMode_1_12 : 48|2@1+ (1,0) [0|3] ""  PC

BO_ 2148827037 M2P_LiquidInfo_1__13: 8 MBMU
 SG_ U2T_BMS_ControlMode_1 : 0|2@1+ (1,0) [0|3] ""  PC
 SG_ T2U_TMS_RunState_1 : 2|2@1+ (1,0) [0|3] ""  PC
 SG_ T2U_TMS_FaultCode_1 : 8|6@1+ (1,0) [0|63] ""  PC
 SG_ T2U_TMS_FaultLevel_1 : 14|2@1+ (1,0) [0|3] ""  PC
 SG_ U2T_BMS_TmptSetPoint_1 : 16|8@1+ (1,-50) [-50|205] "℃"  PC
 SG_ T2U_TMS_OutWaterTemp_1 : 24|8@1+ (1,-50) [-50|205] "℃"  PC
 SG_ T2U_TMS_BackWaterTemp_1 : 32|8@1+ (1,-50) [-50|205] "℃"  PC
 SG_ T2U_TMS_EnvTemp_1 : 40|8@1+ (1,-50) [-50|205] "℃"  PC
 SG_ M2P_TMSCoolingProtectMode_1_13 : 48|2@1+ (1,0) [0|3] ""  PC

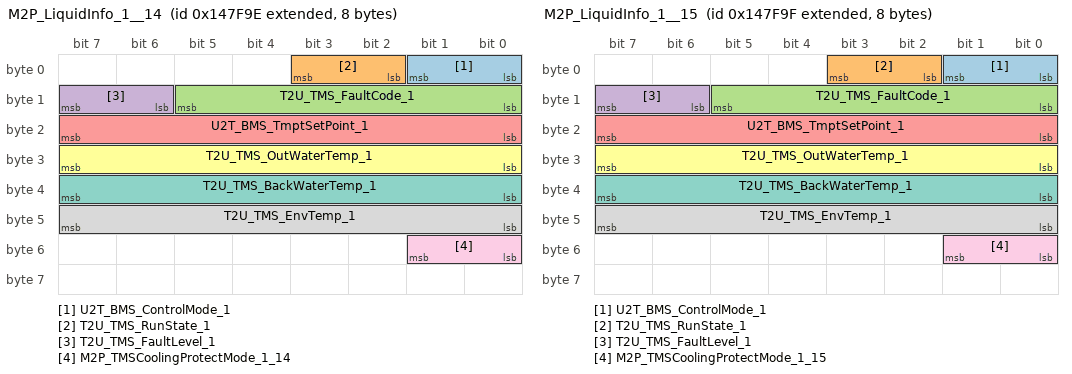
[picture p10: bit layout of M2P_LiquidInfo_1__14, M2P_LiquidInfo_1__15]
BO_ 2148827038 M2P_LiquidInfo_1__14: 8 MBMU
 SG_ U2T_BMS_ControlMode_1 : 0|2@1+ (1,0) [0|3] ""  PC
 SG_ T2U_TMS_RunState_1 : 2|2@1+ (1,0) [0|3] ""  PC
 SG_ T2U_TMS_FaultCode_1 : 8|6@1+ (1,0) [0|63] ""  PC
 SG_ T2U_TMS_FaultLevel_1 : 14|2@1+ (1,0) [0|3] ""  PC
 SG_ U2T_BMS_TmptSetPoint_1 : 16|8@1+ (1,-50) [-50|205] "℃"  PC
 SG_ T2U_TMS_OutWaterTemp_1 : 24|8@1+ (1,-50) [-50|205] "℃"  PC
 SG_ T2U_TMS_BackWaterTemp_1 : 32|8@1+ (1,-50) [-50|205] "℃"  PC
 SG_ T2U_TMS_EnvTemp_1 : 40|8@1+ (1,-50) [-50|205] "℃"  PC
 SG_ M2P_TMSCoolingProtectMode_1_14 : 48|2@1+ (1,0) [0|3] ""  PC

BO_ 2148827039 M2P_LiquidInfo_1__15: 8 MBMU
 SG_ U2T_BMS_ControlMode_1 : 0|2@1+ (1,0) [0|3] ""  PC
 SG_ T2U_TMS_RunState_1 : 2|2@1+ (1,0) [0|3] ""  PC
 SG_ T2U_TMS_FaultCode_1 : 8|6@1+ (1,0) [0|63] ""  PC
 SG_ T2U_TMS_FaultLevel_1 : 14|2@1+ (1,0) [0|3] ""  PC
 SG_ U2T_BMS_TmptSetPoint_1 : 16|8@1+ (1,-50) [-50|205] "℃"  PC
 SG_ T2U_TMS_OutWaterTemp_1 : 24|8@1+ (1,-50) [-50|205] "℃"  PC
 SG_ T2U_TMS_BackWaterTemp_1 : 32|8@1+ (1,-50) [-50|205] "℃"  PC
 SG_ T2U_TMS_EnvTemp_1 : 40|8@1+ (1,-50) [-50|205] "℃"  PC
 SG_ M2P_TMSCoolingProtectMode_1_15 : 48|2@1+ (1,0) [0|3] ""  PC

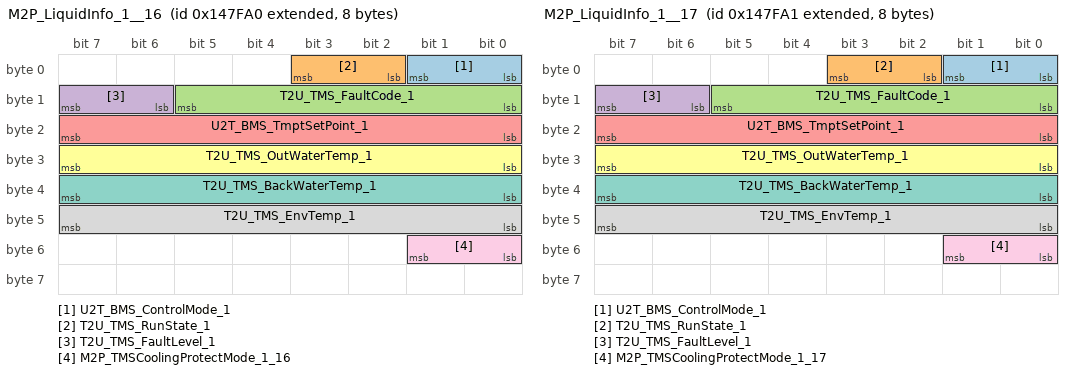
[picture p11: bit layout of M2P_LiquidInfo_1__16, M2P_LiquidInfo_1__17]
BO_ 2148827040 M2P_LiquidInfo_1__16: 8 MBMU
 SG_ U2T_BMS_ControlMode_1 : 0|2@1+ (1,0) [0|3] ""  PC
 SG_ T2U_TMS_RunState_1 : 2|2@1+ (1,0) [0|3] ""  PC
 SG_ T2U_TMS_FaultCode_1 : 8|6@1+ (1,0) [0|63] ""  PC
 SG_ T2U_TMS_FaultLevel_1 : 14|2@1+ (1,0) [0|3] ""  PC
 SG_ U2T_BMS_TmptSetPoint_1 : 16|8@1+ (1,-50) [-50|205] "℃"  PC
 SG_ T2U_TMS_OutWaterTemp_1 : 24|8@1+ (1,-50) [-50|205] "℃"  PC
 SG_ T2U_TMS_BackWaterTemp_1 : 32|8@1+ (1,-50) [-50|205] "℃"  PC
 SG_ T2U_TMS_EnvTemp_1 : 40|8@1+ (1,-50) [-50|205] "℃"  PC
 SG_ M2P_TMSCoolingProtectMode_1_16 : 48|2@1+ (1,0) [0|3] ""  PC

BO_ 2148827041 M2P_LiquidInfo_1__17: 8 MBMU
 SG_ U2T_BMS_ControlMode_1 : 0|2@1+ (1,0) [0|3] ""  PC
 SG_ T2U_TMS_RunState_1 : 2|2@1+ (1,0) [0|3] ""  PC
 SG_ T2U_TMS_FaultCode_1 : 8|6@1+ (1,0) [0|63] ""  PC
 SG_ T2U_TMS_FaultLevel_1 : 14|2@1+ (1,0) [0|3] ""  PC
 SG_ U2T_BMS_TmptSetPoint_1 : 16|8@1+ (1,-50) [-50|205] "℃"  PC
 SG_ T2U_TMS_OutWaterTemp_1 : 24|8@1+ (1,-50) [-50|205] "℃"  PC
 SG_ T2U_TMS_BackWaterTemp_1 : 32|8@1+ (1,-50) [-50|205] "℃"  PC
 SG_ T2U_TMS_EnvTemp_1 : 40|8@1+ (1,-50) [-50|205] "℃"  PC
 SG_ M2P_TMSCoolingProtectMode_1_17 : 48|2@1+ (1,0) [0|3] ""  PC

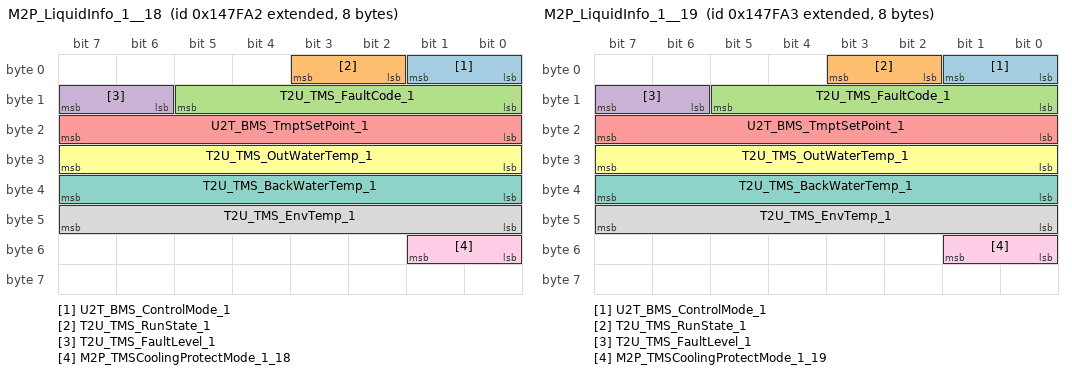
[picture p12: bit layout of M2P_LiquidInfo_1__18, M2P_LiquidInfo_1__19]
BO_ 2148827042 M2P_LiquidInfo_1__18: 8 MBMU
 SG_ U2T_BMS_ControlMode_1 : 0|2@1+ (1,0) [0|3] ""  PC
 SG_ T2U_TMS_RunState_1 : 2|2@1+ (1,0) [0|3] ""  PC
 SG_ T2U_TMS_FaultCode_1 : 8|6@1+ (1,0) [0|63] ""  PC
 SG_ T2U_TMS_FaultLevel_1 : 14|2@1+ (1,0) [0|3] ""  PC
 SG_ U2T_BMS_TmptSetPoint_1 : 16|8@1+ (1,-50) [-50|205] "℃"  PC
 SG_ T2U_TMS_OutWaterTemp_1 : 24|8@1+ (1,-50) [-50|205] "℃"  PC
 SG_ T2U_TMS_BackWaterTemp_1 : 32|8@1+ (1,-50) [-50|205] "℃"  PC
 SG_ T2U_TMS_EnvTemp_1 : 40|8@1+ (1,-50) [-50|205] "℃"  PC
 SG_ M2P_TMSCoolingProtectMode_1_18 : 48|2@1+ (1,0) [0|3] ""  PC

BO_ 2148827043 M2P_LiquidInfo_1__19: 8 MBMU
 SG_ U2T_BMS_ControlMode_1 : 0|2@1+ (1,0) [0|3] ""  PC
 SG_ T2U_TMS_RunState_1 : 2|2@1+ (1,0) [0|3] ""  PC
 SG_ T2U_TMS_FaultCode_1 : 8|6@1+ (1,0) [0|63] ""  PC
 SG_ T2U_TMS_FaultLevel_1 : 14|2@1+ (1,0) [0|3] ""  PC
 SG_ U2T_BMS_TmptSetPoint_1 : 16|8@1+ (1,-50) [-50|205] "℃"  PC
 SG_ T2U_TMS_OutWaterTemp_1 : 24|8@1+ (1,-50) [-50|205] "℃"  PC
 SG_ T2U_TMS_BackWaterTemp_1 : 32|8@1+ (1,-50) [-50|205] "℃"  PC
 SG_ T2U_TMS_EnvTemp_1 : 40|8@1+ (1,-50) [-50|205] "℃"  PC
 SG_ M2P_TMSCoolingProtectMode_1_19 : 48|2@1+ (1,0) [0|3] ""  PC

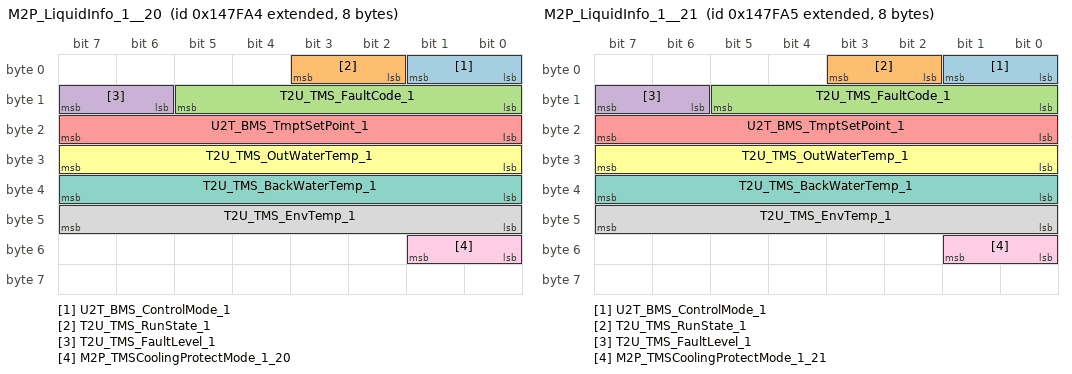
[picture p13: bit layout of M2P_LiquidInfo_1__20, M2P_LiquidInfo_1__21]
BO_ 2148827044 M2P_LiquidInfo_1__20: 8 MBMU
 SG_ U2T_BMS_ControlMode_1 : 0|2@1+ (1,0) [0|3] ""  PC
 SG_ T2U_TMS_RunState_1 : 2|2@1+ (1,0) [0|3] ""  PC
 SG_ T2U_TMS_FaultCode_1 : 8|6@1+ (1,0) [0|63] ""  PC
 SG_ T2U_TMS_FaultLevel_1 : 14|2@1+ (1,0) [0|3] ""  PC
 SG_ U2T_BMS_TmptSetPoint_1 : 16|8@1+ (1,-50) [-50|205] "℃"  PC
 SG_ T2U_TMS_OutWaterTemp_1 : 24|8@1+ (1,-50) [-50|205] "℃"  PC
 SG_ T2U_TMS_BackWaterTemp_1 : 32|8@1+ (1,-50) [-50|205] "℃"  PC
 SG_ T2U_TMS_EnvTemp_1 : 40|8@1+ (1,-50) [-50|205] "℃"  PC
 SG_ M2P_TMSCoolingProtectMode_1_20 : 48|2@1+ (1,0) [0|3] ""  PC

BO_ 2148827045 M2P_LiquidInfo_1__21: 8 MBMU
 SG_ U2T_BMS_ControlMode_1 : 0|2@1+ (1,0) [0|3] ""  PC
 SG_ T2U_TMS_RunState_1 : 2|2@1+ (1,0) [0|3] ""  PC
 SG_ T2U_TMS_FaultCode_1 : 8|6@1+ (1,0) [0|63] ""  PC
 SG_ T2U_TMS_FaultLevel_1 : 14|2@1+ (1,0) [0|3] ""  PC
 SG_ U2T_BMS_TmptSetPoint_1 : 16|8@1+ (1,-50) [-50|205] "℃"  PC
 SG_ T2U_TMS_OutWaterTemp_1 : 24|8@1+ (1,-50) [-50|205] "℃"  PC
 SG_ T2U_TMS_BackWaterTemp_1 : 32|8@1+ (1,-50) [-50|205] "℃"  PC
 SG_ T2U_TMS_EnvTemp_1 : 40|8@1+ (1,-50) [-50|205] "℃"  PC
 SG_ M2P_TMSCoolingProtectMode_1_21 : 48|2@1+ (1,0) [0|3] ""  PC

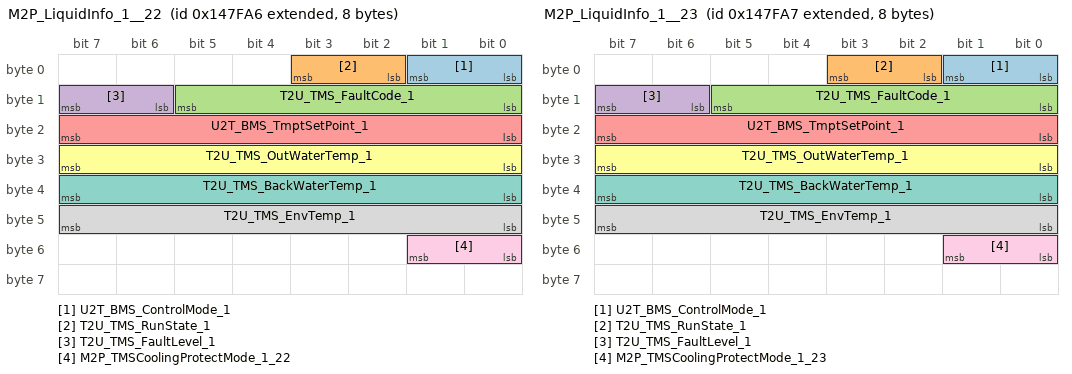
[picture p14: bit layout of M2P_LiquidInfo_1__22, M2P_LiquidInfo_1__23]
BO_ 2148827046 M2P_LiquidInfo_1__22: 8 MBMU
 SG_ U2T_BMS_ControlMode_1 : 0|2@1+ (1,0) [0|3] ""  PC
 SG_ T2U_TMS_RunState_1 : 2|2@1+ (1,0) [0|3] ""  PC
 SG_ T2U_TMS_FaultCode_1 : 8|6@1+ (1,0) [0|63] ""  PC
 SG_ T2U_TMS_FaultLevel_1 : 14|2@1+ (1,0) [0|3] ""  PC
 SG_ U2T_BMS_TmptSetPoint_1 : 16|8@1+ (1,-50) [-50|205] "℃"  PC
 SG_ T2U_TMS_OutWaterTemp_1 : 24|8@1+ (1,-50) [-50|205] "℃"  PC
 SG_ T2U_TMS_BackWaterTemp_1 : 32|8@1+ (1,-50) [-50|205] "℃"  PC
 SG_ T2U_TMS_EnvTemp_1 : 40|8@1+ (1,-50) [-50|205] "℃"  PC
 SG_ M2P_TMSCoolingProtectMode_1_22 : 48|2@1+ (1,0) [0|3] ""  PC

BO_ 2148827047 M2P_LiquidInfo_1__23: 8 MBMU
 SG_ U2T_BMS_ControlMode_1 : 0|2@1+ (1,0) [0|3] ""  PC
 SG_ T2U_TMS_RunState_1 : 2|2@1+ (1,0) [0|3] ""  PC
 SG_ T2U_TMS_FaultCode_1 : 8|6@1+ (1,0) [0|63] ""  PC
 SG_ T2U_TMS_FaultLevel_1 : 14|2@1+ (1,0) [0|3] ""  PC
 SG_ U2T_BMS_TmptSetPoint_1 : 16|8@1+ (1,-50) [-50|205] "℃"  PC
 SG_ T2U_TMS_OutWaterTemp_1 : 24|8@1+ (1,-50) [-50|205] "℃"  PC
 SG_ T2U_TMS_BackWaterTemp_1 : 32|8@1+ (1,-50) [-50|205] "℃"  PC
 SG_ T2U_TMS_EnvTemp_1 : 40|8@1+ (1,-50) [-50|205] "℃"  PC
 SG_ M2P_TMSCoolingProtectMode_1_23 : 48|2@1+ (1,0) [0|3] ""  PC

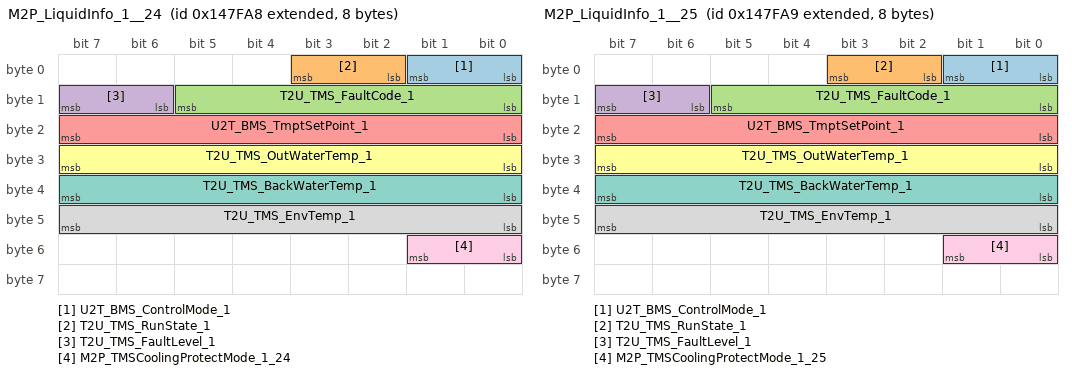
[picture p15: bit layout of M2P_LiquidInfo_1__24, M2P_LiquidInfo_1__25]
BO_ 2148827048 M2P_LiquidInfo_1__24: 8 MBMU
 SG_ U2T_BMS_ControlMode_1 : 0|2@1+ (1,0) [0|3] ""  PC
 SG_ T2U_TMS_RunState_1 : 2|2@1+ (1,0) [0|3] ""  PC
 SG_ T2U_TMS_FaultCode_1 : 8|6@1+ (1,0) [0|63] ""  PC
 SG_ T2U_TMS_FaultLevel_1 : 14|2@1+ (1,0) [0|3] ""  PC
 SG_ U2T_BMS_TmptSetPoint_1 : 16|8@1+ (1,-50) [-50|205] "℃"  PC
 SG_ T2U_TMS_OutWaterTemp_1 : 24|8@1+ (1,-50) [-50|205] "℃"  PC
 SG_ T2U_TMS_BackWaterTemp_1 : 32|8@1+ (1,-50) [-50|205] "℃"  PC
 SG_ T2U_TMS_EnvTemp_1 : 40|8@1+ (1,-50) [-50|205] "℃"  PC
 SG_ M2P_TMSCoolingProtectMode_1_24 : 48|2@1+ (1,0) [0|3] ""  PC

BO_ 2148827049 M2P_LiquidInfo_1__25: 8 MBMU
 SG_ U2T_BMS_ControlMode_1 : 0|2@1+ (1,0) [0|3] ""  PC
 SG_ T2U_TMS_RunState_1 : 2|2@1+ (1,0) [0|3] ""  PC
 SG_ T2U_TMS_FaultCode_1 : 8|6@1+ (1,0) [0|63] ""  PC
 SG_ T2U_TMS_FaultLevel_1 : 14|2@1+ (1,0) [0|3] ""  PC
 SG_ U2T_BMS_TmptSetPoint_1 : 16|8@1+ (1,-50) [-50|205] "℃"  PC
 SG_ T2U_TMS_OutWaterTemp_1 : 24|8@1+ (1,-50) [-50|205] "℃"  PC
 SG_ T2U_TMS_BackWaterTemp_1 : 32|8@1+ (1,-50) [-50|205] "℃"  PC
 SG_ T2U_TMS_EnvTemp_1 : 40|8@1+ (1,-50) [-50|205] "℃"  PC
 SG_ M2P_TMSCoolingProtectMode_1_25 : 48|2@1+ (1,0) [0|3] ""  PC

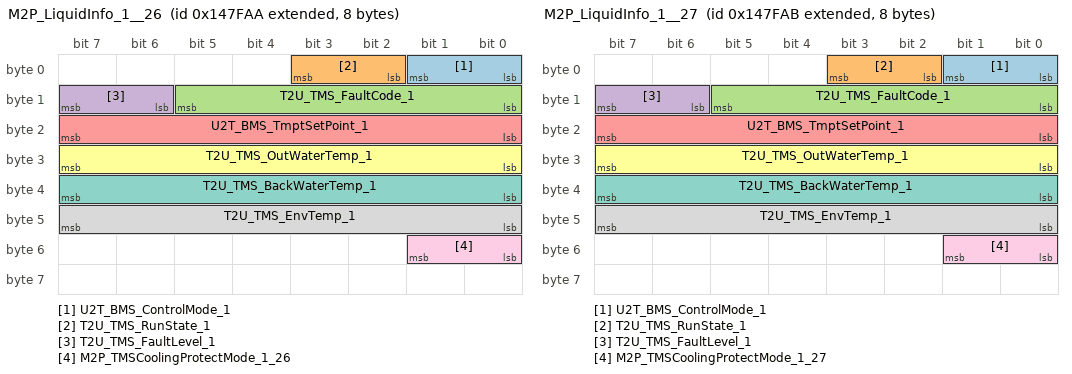
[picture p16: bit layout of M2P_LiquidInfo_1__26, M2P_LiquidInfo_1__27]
BO_ 2148827050 M2P_LiquidInfo_1__26: 8 MBMU
 SG_ U2T_BMS_ControlMode_1 : 0|2@1+ (1,0) [0|3] ""  PC
 SG_ T2U_TMS_RunState_1 : 2|2@1+ (1,0) [0|3] ""  PC
 SG_ T2U_TMS_FaultCode_1 : 8|6@1+ (1,0) [0|63] ""  PC
 SG_ T2U_TMS_FaultLevel_1 : 14|2@1+ (1,0) [0|3] ""  PC
 SG_ U2T_BMS_TmptSetPoint_1 : 16|8@1+ (1,-50) [-50|205] "℃"  PC
 SG_ T2U_TMS_OutWaterTemp_1 : 24|8@1+ (1,-50) [-50|205] "℃"  PC
 SG_ T2U_TMS_BackWaterTemp_1 : 32|8@1+ (1,-50) [-50|205] "℃"  PC
 SG_ T2U_TMS_EnvTemp_1 : 40|8@1+ (1,-50) [-50|205] "℃"  PC
 SG_ M2P_TMSCoolingProtectMode_1_26 : 48|2@1+ (1,0) [0|3] ""  PC

BO_ 2148827051 M2P_LiquidInfo_1__27: 8 MBMU
 SG_ U2T_BMS_ControlMode_1 : 0|2@1+ (1,0) [0|3] ""  PC
 SG_ T2U_TMS_RunState_1 : 2|2@1+ (1,0) [0|3] ""  PC
 SG_ T2U_TMS_FaultCode_1 : 8|6@1+ (1,0) [0|63] ""  PC
 SG_ T2U_TMS_FaultLevel_1 : 14|2@1+ (1,0) [0|3] ""  PC
 SG_ U2T_BMS_TmptSetPoint_1 : 16|8@1+ (1,-50) [-50|205] "℃"  PC
 SG_ T2U_TMS_OutWaterTemp_1 : 24|8@1+ (1,-50) [-50|205] "℃"  PC
 SG_ T2U_TMS_BackWaterTemp_1 : 32|8@1+ (1,-50) [-50|205] "℃"  PC
 SG_ T2U_TMS_EnvTemp_1 : 40|8@1+ (1,-50) [-50|205] "℃"  PC
 SG_ M2P_TMSCoolingProtectMode_1_27 : 48|2@1+ (1,0) [0|3] ""  PC

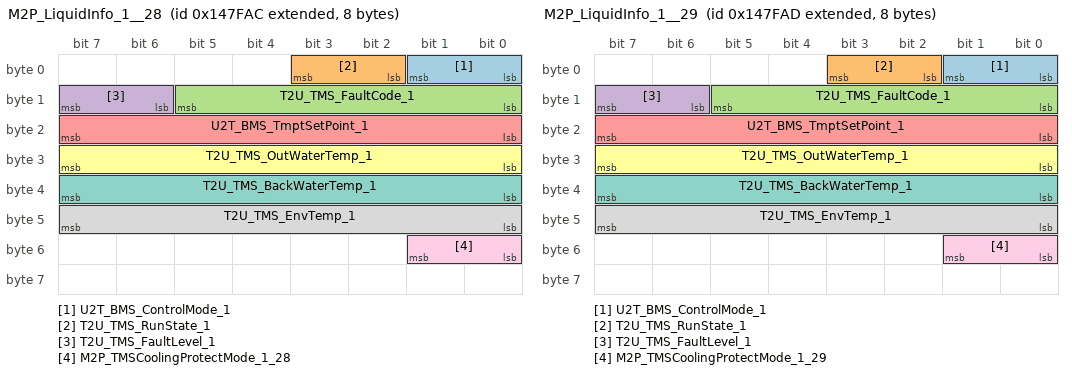
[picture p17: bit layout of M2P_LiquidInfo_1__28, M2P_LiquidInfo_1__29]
BO_ 2148827052 M2P_LiquidInfo_1__28: 8 MBMU
 SG_ U2T_BMS_ControlMode_1 : 0|2@1+ (1,0) [0|3] ""  PC
 SG_ T2U_TMS_RunState_1 : 2|2@1+ (1,0) [0|3] ""  PC
 SG_ T2U_TMS_FaultCode_1 : 8|6@1+ (1,0) [0|63] ""  PC
 SG_ T2U_TMS_FaultLevel_1 : 14|2@1+ (1,0) [0|3] ""  PC
 SG_ U2T_BMS_TmptSetPoint_1 : 16|8@1+ (1,-50) [-50|205] "℃"  PC
 SG_ T2U_TMS_OutWaterTemp_1 : 24|8@1+ (1,-50) [-50|205] "℃"  PC
 SG_ T2U_TMS_BackWaterTemp_1 : 32|8@1+ (1,-50) [-50|205] "℃"  PC
 SG_ T2U_TMS_EnvTemp_1 : 40|8@1+ (1,-50) [-50|205] "℃"  PC
 SG_ M2P_TMSCoolingProtectMode_1_28 : 48|2@1+ (1,0) [0|3] ""  PC

BO_ 2148827053 M2P_LiquidInfo_1__29: 8 MBMU
 SG_ U2T_BMS_ControlMode_1 : 0|2@1+ (1,0) [0|3] ""  PC
 SG_ T2U_TMS_RunState_1 : 2|2@1+ (1,0) [0|3] ""  PC
 SG_ T2U_TMS_FaultCode_1 : 8|6@1+ (1,0) [0|63] ""  PC
 SG_ T2U_TMS_FaultLevel_1 : 14|2@1+ (1,0) [0|3] ""  PC
 SG_ U2T_BMS_TmptSetPoint_1 : 16|8@1+ (1,-50) [-50|205] "℃"  PC
 SG_ T2U_TMS_OutWaterTemp_1 : 24|8@1+ (1,-50) [-50|205] "℃"  PC
 SG_ T2U_TMS_BackWaterTemp_1 : 32|8@1+ (1,-50) [-50|205] "℃"  PC
 SG_ T2U_TMS_EnvTemp_1 : 40|8@1+ (1,-50) [-50|205] "℃"  PC
 SG_ M2P_TMSCoolingProtectMode_1_29 : 48|2@1+ (1,0) [0|3] ""  PC

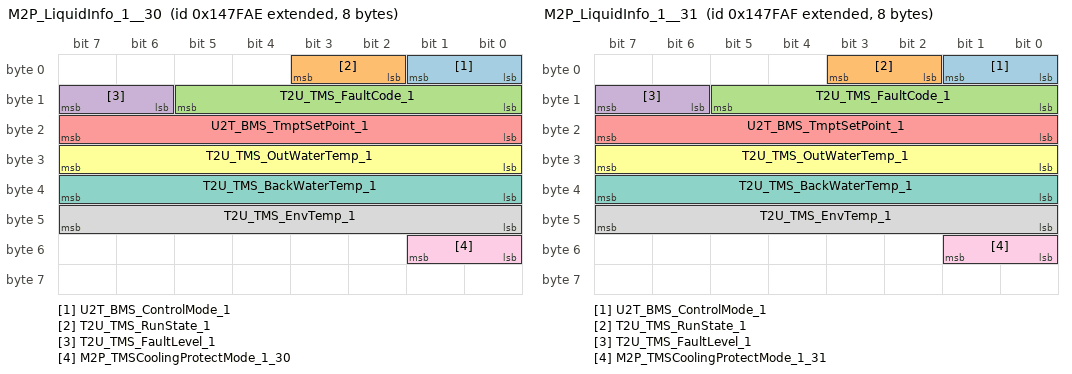
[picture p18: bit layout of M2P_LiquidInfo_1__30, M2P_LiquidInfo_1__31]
BO_ 2148827054 M2P_LiquidInfo_1__30: 8 MBMU
 SG_ U2T_BMS_ControlMode_1 : 0|2@1+ (1,0) [0|3] ""  PC
 SG_ T2U_TMS_RunState_1 : 2|2@1+ (1,0) [0|3] ""  PC
 SG_ T2U_TMS_FaultCode_1 : 8|6@1+ (1,0) [0|63] ""  PC
 SG_ T2U_TMS_FaultLevel_1 : 14|2@1+ (1,0) [0|3] ""  PC
 SG_ U2T_BMS_TmptSetPoint_1 : 16|8@1+ (1,-50) [-50|205] "℃"  PC
 SG_ T2U_TMS_OutWaterTemp_1 : 24|8@1+ (1,-50) [-50|205] "℃"  PC
 SG_ T2U_TMS_BackWaterTemp_1 : 32|8@1+ (1,-50) [-50|205] "℃"  PC
 SG_ T2U_TMS_EnvTemp_1 : 40|8@1+ (1,-50) [-50|205] "℃"  PC
 SG_ M2P_TMSCoolingProtectMode_1_30 : 48|2@1+ (1,0) [0|3] ""  PC

BO_ 2148827055 M2P_LiquidInfo_1__31: 8 MBMU
 SG_ U2T_BMS_ControlMode_1 : 0|2@1+ (1,0) [0|3] ""  PC
 SG_ T2U_TMS_RunState_1 : 2|2@1+ (1,0) [0|3] ""  PC
 SG_ T2U_TMS_FaultCode_1 : 8|6@1+ (1,0) [0|63] ""  PC
 SG_ T2U_TMS_FaultLevel_1 : 14|2@1+ (1,0) [0|3] ""  PC
 SG_ U2T_BMS_TmptSetPoint_1 : 16|8@1+ (1,-50) [-50|205] "℃"  PC
 SG_ T2U_TMS_OutWaterTemp_1 : 24|8@1+ (1,-50) [-50|205] "℃"  PC
 SG_ T2U_TMS_BackWaterTemp_1 : 32|8@1+ (1,-50) [-50|205] "℃"  PC
 SG_ T2U_TMS_EnvTemp_1 : 40|8@1+ (1,-50) [-50|205] "℃"  PC
 SG_ M2P_TMSCoolingProtectMode_1_31 : 48|2@1+ (1,0) [0|3] ""  PC

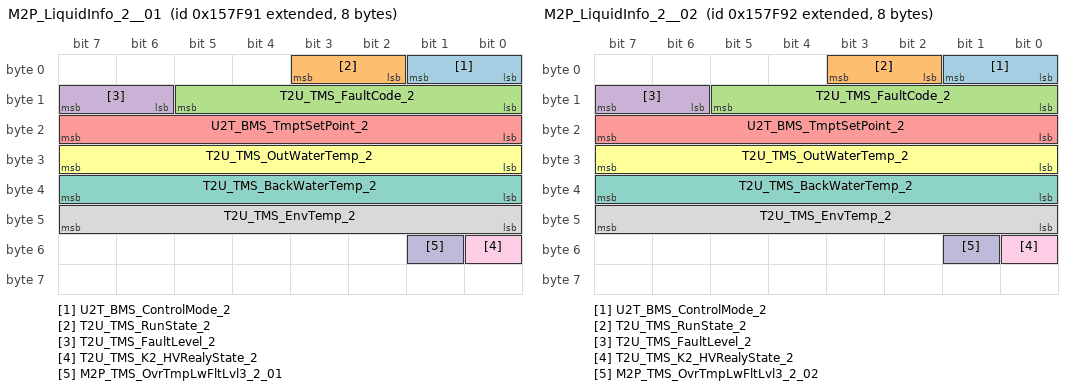
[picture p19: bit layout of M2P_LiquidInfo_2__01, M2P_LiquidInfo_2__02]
BO_ 2148892561 M2P_LiquidInfo_2__01: 8 MBMU
 SG_ U2T_BMS_ControlMode_2 : 0|2@1+ (1,0) [0|3] ""  PC
 SG_ T2U_TMS_RunState_2 : 2|2@1+ (1,0) [0|3] ""  PC
 SG_ T2U_TMS_FaultCode_2 : 8|6@1+ (1,0) [0|63] ""  PC
 SG_ T2U_TMS_FaultLevel_2 : 14|2@1+ (1,0) [0|3] ""  PC
 SG_ U2T_BMS_TmptSetPoint_2 : 16|8@1+ (1,-50) [-50|205] "℃"  PC
 SG_ T2U_TMS_OutWaterTemp_2 : 24|8@1+ (1,-50) [-50|205] "℃"  PC
 SG_ T2U_TMS_BackWaterTemp_2 : 32|8@1+ (1,-50) [-50|205] "℃"  PC
 SG_ T2U_TMS_EnvTemp_2 : 40|8@1+ (1,-50) [-50|205] "℃"  PC
 SG_ T2U_TMS_K2_HVRealyState_2 : 48|1@1+ (1,0) [0|1] ""  PC
 SG_ M2P_TMS_OvrTmpLwFltLvl3_2_01 : 49|1@1+ (1,0) [0|1] ""  PC

BO_ 2148892562 M2P_LiquidInfo_2__02: 8 MBMU
 SG_ U2T_BMS_ControlMode_2 : 0|2@1+ (1,0) [0|3] ""  PC
 SG_ T2U_TMS_RunState_2 : 2|2@1+ (1,0) [0|3] ""  PC
 SG_ T2U_TMS_FaultCode_2 : 8|6@1+ (1,0) [0|63] ""  PC
 SG_ T2U_TMS_FaultLevel_2 : 14|2@1+ (1,0) [0|3] ""  PC
 SG_ U2T_BMS_TmptSetPoint_2 : 16|8@1+ (1,-50) [-50|205] "℃"  PC
 SG_ T2U_TMS_OutWaterTemp_2 : 24|8@1+ (1,-50) [-50|205] "℃"  PC
 SG_ T2U_TMS_BackWaterTemp_2 : 32|8@1+ (1,-50) [-50|205] "℃"  PC
 SG_ T2U_TMS_EnvTemp_2 : 40|8@1+ (1,-50) [-50|205] "℃"  PC
 SG_ T2U_TMS_K2_HVRealyState_2 : 48|1@1+ (1,0) [0|1] ""  PC
 SG_ M2P_TMS_OvrTmpLwFltLvl3_2_02 : 49|1@1+ (1,0) [0|1] ""  PC

CM_ SG_ 2148749671 CellHeatMode_Status "BMS自加热的状态";
CM_ SG_ 2148749671 CellHeatMode_PermitStatus "SBMU反馈自加热允许状态";
CM_ SG_ 2148749672 CellHeatMode_Status "BMS自加热的状态";
CM_ SG_ 2148749672 CellHeatMode_PermitStatus "SBMU反馈自加热允许状态";
CM_ SG_ 2148749673 CellHeatMode_Status "BMS自加热的状态";
CM_ SG_ 2148749673 CellHeatMode_PermitStatus "SBMU反馈自加热允许状态";
CM_ SG_ 2148749674 CellHeatMode_Status "BMS自加热的状态";
CM_ SG_ 2148749674 CellHeatMode_PermitStatus "SBMU反馈自加热允许状态";
CM_ SG_ 2148749675 CellHeatMode_Status "BMS自加热的状态";
CM_ SG_ 2148749675 CellHeatMode_PermitStatus "SBMU反馈自加热允许状态";
CM_ SG_ 2148749676 CellHeatMode_Status "BMS自加热的状态";
CM_ SG_ 2148749676 CellHeatMode_PermitStatus "SBMU反馈自加热允许状态";
CM_ SG_ 2148749677 CellHeatMode_Status "BMS自加热的状态";
CM_ SG_ 2148749677 CellHeatMode_PermitStatus "SBMU反馈自加热允许状态";
CM_ SG_ 2148749678 CellHeatMode_Status "BMS自加热的状态";
CM_ SG_ 2148749678 CellHeatMode_PermitStatus "SBMU反馈自加热允许状态";
CM_ SG_ 2148749679 CellHeatMode_Status "BMS自加热的状态";
CM_ SG_ 2148749679 CellHeatMode_PermitStatus "SBMU反馈自加热允许状态";
CM_ SG_ 2148749680 CellHeatMode_Status "BMS自加热的状态";
CM_ SG_ 2148749680 CellHeatMode_PermitStatus "SBMU反馈自加热允许状态";
CM_ SG_ 2148749681 CellHeatMode_Status "BMS自加热的状态";
CM_ SG_ 2148749681 CellHeatMode_PermitStatus "SBMU反馈自加热允许状态";
CM_ SG_ 2148749682 CellHeatMode_Status "BMS自加热的状态";
CM_ SG_ 2148749682 CellHeatMode_PermitStatus "SBMU反馈自加热允许状态";
CM_ SG_ 2148749683 CellHeatMode_Status "BMS自加热的状态";
CM_ SG_ 2148749683 CellHeatMode_PermitStatus "SBMU反馈自加热允许状态";
CM_ SG_ 2148749684 CellHeatMode_Status "BMS自加热的状态";
CM_ SG_ 2148749684 CellHeatMode_PermitStatus "SBMU反馈自加热允许状态";
CM_ SG_ 2148749685 CellHeatMode_Status "BMS自加热的状态";
CM_ SG_ 2148749685 CellHeatMode_PermitStatus "SBMU反馈自加热允许状态";
CM_ SG_ 2148749686 CellHeatMode_Status "BMS自加热的状态";
CM_ SG_ 2148749686 CellHeatMode_PermitStatus "SBMU反馈自加热允许状态";
CM_ SG_ 2148749687 CellHeatMode_Status "BMS自加热的状态";
CM_ SG_ 2148749687 CellHeatMode_PermitStatus "SBMU反馈自加热允许状态";
CM_ SG_ 2148749688 CellHeatMode_Status "BMS自加热的状态";
CM_ SG_ 2148749688 CellHeatMode_PermitStatus "SBMU反馈自加热允许状态";
CM_ SG_ 2148749689 CellHeatMode_Status "BMS自加热的状态";
CM_ SG_ 2148749689 CellHeatMode_PermitStatus "SBMU反馈自加热允许状态";
CM_ SG_ 2148749690 CellHeatMode_Status "BMS自加热的状态";
CM_ SG_ 2148749690 CellHeatMode_PermitStatus "SBMU反馈自加热允许状态";
CM_ SG_ 2148749691 CellHeatMode_Status "BMS自加热的状态";
CM_ SG_ 2148749691 CellHeatMode_PermitStatus "SBMU反馈自加热允许状态";
CM_ SG_ 2148749692 CellHeatMode_Status "BMS自加热的状态";
CM_ SG_ 2148749692 CellHeatMode_PermitStatus "SBMU反馈自加热允许状态";
CM_ SG_ 2148749693 CellHeatMode_Status "BMS自加热的状态";
CM_ SG_ 2148749693 CellHeatMode_PermitStatus "SBMU反馈自加热允许状态";
CM_ SG_ 2148749694 CellHeatMode_Status "BMS自加热的状态";
CM_ SG_ 2148749694 CellHeatMode_PermitStatus "SBMU反馈自加热允许状态";
CM_ SG_ 2148749695 CellHeatMode_Status "BMS自加热的状态";
CM_ SG_ 2148749695 CellHeatMode_PermitStatus "SBMU反馈自加热允许状态";
CM_ SG_ 2148958097 M2S_CMD6_Reserve1_01 "平台预留报文";
CM_ SG_ 2148958097 M2S_CMD6_Reserve2_01 "平台预留报文";
CM_ SG_ 2148958097 M2S_CMD6_Reserve3_01 "平台预留报文";
CM_ SG_ 2148958097 M2S_CMD6_Reserve4_01 "平台预留报文";
CM_ SG_ 2148958097 M2S_CMD6_Reserve5_01 "平台预留报文";
CM_ SG_ 2148958097 M2S_CMD6_Reserve6_01 "平台预留报文";
CM_ SG_ 2148958097 M2S_CMD6_Reserve7_01 "平台预留报文";
CM_ SG_ 2148958097 M2S_CMD6_Reserve8_01 "平台预留报文";
CM_ SG_ 2148958098 M2S_CMD6_Reserve1_02 "平台预留报文";
CM_ SG_ 2148958098 M2S_CMD6_Reserve2_02 "平台预留报文";
CM_ SG_ 2148958098 M2S_CMD6_Reserve3_02 "平台预留报文";
CM_ SG_ 2148958098 M2S_CMD6_Reserve4_02 "平台预留报文";
CM_ SG_ 2148958098 M2S_CMD6_Reserve5_02 "平台预留报文";
CM_ SG_ 2148958098 M2S_CMD6_Reserve6_02 "平台预留报文";
CM_ SG_ 2148958098 M2S_CMD6_Reserve7_02 "平台预留报文";
CM_ SG_ 2148958098 M2S_CMD6_Reserve8_02 "平台预留报文";
CM_ SG_ 2148958099 M2S_CMD6_Reserve1_03 "平台预留报文";
CM_ SG_ 2148958099 M2S_CMD6_Reserve2_03 "平台预留报文";
CM_ SG_ 2148958099 M2S_CMD6_Reserve3_03 "平台预留报文";
CM_ SG_ 2148958099 M2S_CMD6_Reserve4_03 "平台预留报文";
CM_ SG_ 2148958099 M2S_CMD6_Reserve5_03 "平台预留报文";
CM_ SG_ 2148958099 M2S_CMD6_Reserve6_03 "平台预留报文";
CM_ SG_ 2148958099 M2S_CMD6_Reserve7_03 "平台预留报文";
CM_ SG_ 2148958099 M2S_CMD6_Reserve8_03 "平台预留报文";
CM_ SG_ 2148958100 M2S_CMD6_Reserve1_04 "平台预留报文";
CM_ SG_ 2148958100 M2S_CMD6_Reserve2_04 "平台预留报文";
CM_ SG_ 2148958100 M2S_CMD6_Reserve3_04 "平台预留报文";
CM_ SG_ 2148958100 M2S_CMD6_Reserve4_04 "平台预留报文";
CM_ SG_ 2148958100 M2S_CMD6_Reserve5_04 "平台预留报文";
CM_ SG_ 2148958100 M2S_CMD6_Reserve6_04 "平台预留报文";
CM_ SG_ 2148958100 M2S_CMD6_Reserve7_04 "平台预留报文";
CM_ SG_ 2148958100 M2S_CMD6_Reserve8_04 "平台预留报文";
CM_ SG_ 2148958101 M2S_CMD6_Reserve1_05 "平台预留报文";
CM_ SG_ 2148958101 M2S_CMD6_Reserve2_05 "平台预留报文";
CM_ SG_ 2148958101 M2S_CMD6_Reserve3_05 "平台预留报文";
CM_ SG_ 2148958101 M2S_CMD6_Reserve4_05 "平台预留报文";
CM_ SG_ 2148958101 M2S_CMD6_Reserve5_05 "平台预留报文";
CM_ SG_ 2148958101 M2S_CMD6_Reserve6_05 "平台预留报文";
CM_ SG_ 2148958101 M2S_CMD6_Reserve7_05 "平台预留报文";
CM_ SG_ 2148958101 M2S_CMD6_Reserve8_05 "平台预留报文";
CM_ SG_ 2148958102 M2S_CMD6_Reserve1_06 "平台预留报文";
CM_ SG_ 2148958102 M2S_CMD6_Reserve2_06 "平台预留报文";
CM_ SG_ 2148958102 M2S_CMD6_Reserve3_06 "平台预留报文";
CM_ SG_ 2148958102 M2S_CMD6_Reserve4_06 "平台预留报文";
CM_ SG_ 2148958102 M2S_CMD6_Reserve5_06 "平台预留报文";
CM_ SG_ 2148958102 M2S_CMD6_Reserve6_06 "平台预留报文";
CM_ SG_ 2148958102 M2S_CMD6_Reserve7_06 "平台预留报文";
CM_ SG_ 2148958102 M2S_CMD6_Reserve8_06 "平台预留报文";
CM_ SG_ 2148958103 M2S_CMD6_Reserve1_07 "平台预留报文";
CM_ SG_ 2148958103 M2S_CMD6_Reserve2_07 "平台预留报文";
CM_ SG_ 2148958103 M2S_CMD6_Reserve3_07 "平台预留报文";
CM_ SG_ 2148958103 M2S_CMD6_Reserve4_07 "平台预留报文";
CM_ SG_ 2148958103 M2S_CMD6_Reserve5_07 "平台预留报文";
CM_ SG_ 2148958103 M2S_CMD6_Reserve6_07 "平台预留报文";
CM_ SG_ 2148958103 M2S_CMD6_Reserve7_07 "平台预留报文";
CM_ SG_ 2148958103 M2S_CMD6_Reserve8_07 "平台预留报文";
CM_ SG_ 2148958104 M2S_CMD6_Reserve1_08 "平台预留报文";
CM_ SG_ 2148958104 M2S_CMD6_Reserve2_08 "平台预留报文";
CM_ SG_ 2148958104 M2S_CMD6_Reserve3_08 "平台预留报文";
CM_ SG_ 2148958104 M2S_CMD6_Reserve4_08 "平台预留报文";
CM_ SG_ 2148958104 M2S_CMD6_Reserve5_08 "平台预留报文";
CM_ SG_ 2148958104 M2S_CMD6_Reserve6_08 "平台预留报文";
CM_ SG_ 2148958104 M2S_CMD6_Reserve7_08 "平台预留报文";
CM_ SG_ 2148958104 M2S_CMD6_Reserve8_08 "平台预留报文";
CM_ SG_ 2148958105 M2S_CMD6_Reserve1_09 "平台预留报文";
CM_ SG_ 2148958105 M2S_CMD6_Reserve2_09 "平台预留报文";
CM_ SG_ 2148958105 M2S_CMD6_Reserve3_09 "平台预留报文";
CM_ SG_ 2148958105 M2S_CMD6_Reserve4_09 "平台预留报文";
CM_ SG_ 2148958105 M2S_CMD6_Reserve5_09 "平台预留报文";
CM_ SG_ 2148958105 M2S_CMD6_Reserve6_09 "平台预留报文";
CM_ SG_ 2148958105 M2S_CMD6_Reserve7_09 "平台预留报文";
CM_ SG_ 2148958105 M2S_CMD6_Reserve8_09 "平台预留报文";
CM_ SG_ 2148958106 M2S_CMD6_Reserve1_10 "平台预留报文";
CM_ SG_ 2148958106 M2S_CMD6_Reserve2_10 "平台预留报文";
CM_ SG_ 2148958106 M2S_CMD6_Reserve3_10 "平台预留报文";
CM_ SG_ 2148958106 M2S_CMD6_Reserve4_10 "平台预留报文";
CM_ SG_ 2148958106 M2S_CMD6_Reserve5_10 "平台预留报文";
CM_ SG_ 2148958106 M2S_CMD6_Reserve6_10 "平台预留报文";
CM_ SG_ 2148958106 M2S_CMD6_Reserve7_10 "平台预留报文";
CM_ SG_ 2148958106 M2S_CMD6_Reserve8_10 "平台预留报文";
CM_ SG_ 2148958107 M2S_CMD6_Reserve1_11 "平台预留报文";
CM_ SG_ 2148958107 M2S_CMD6_Reserve2_11 "平台预留报文";
CM_ SG_ 2148958107 M2S_CMD6_Reserve3_11 "平台预留报文";
CM_ SG_ 2148958107 M2S_CMD6_Reserve4_11 "平台预留报文";
CM_ SG_ 2148958107 M2S_CMD6_Reserve5_11 "平台预留报文";
CM_ SG_ 2148958107 M2S_CMD6_Reserve6_11 "平台预留报文";
CM_ SG_ 2148958107 M2S_CMD6_Reserve7_11 "平台预留报文";
CM_ SG_ 2148958107 M2S_CMD6_Reserve8_11 "平台预留报文";
CM_ SG_ 2148958108 M2S_CMD6_Reserve1_12 "平台预留报文";
CM_ SG_ 2148958108 M2S_CMD6_Reserve2_12 "平台预留报文";
CM_ SG_ 2148958108 M2S_CMD6_Reserve3_12 "平台预留报文";
CM_ SG_ 2148958108 M2S_CMD6_Reserve4_12 "平台预留报文";
CM_ SG_ 2148958108 M2S_CMD6_Reserve5_12 "平台预留报文";
CM_ SG_ 2148958108 M2S_CMD6_Reserve6_12 "平台预留报文";
CM_ SG_ 2148958108 M2S_CMD6_Reserve7_12 "平台预留报文";
CM_ SG_ 2148958108 M2S_CMD6_Reserve8_12 "平台预留报文";
CM_ SG_ 2148958109 M2S_CMD6_Reserve1_13 "平台预留报文";
CM_ SG_ 2148958109 M2S_CMD6_Reserve2_13 "平台预留报文";
CM_ SG_ 2148958109 M2S_CMD6_Reserve3_13 "平台预留报文";
CM_ SG_ 2148958109 M2S_CMD6_Reserve4_13 "平台预留报文";
CM_ SG_ 2148958109 M2S_CMD6_Reserve5_13 "平台预留报文";
CM_ SG_ 2148958109 M2S_CMD6_Reserve6_13 "平台预留报文";
CM_ SG_ 2148958109 M2S_CMD6_Reserve7_13 "平台预留报文";
CM_ SG_ 2148958109 M2S_CMD6_Reserve8_13 "平台预留报文";
CM_ SG_ 2148958110 M2S_CMD6_Reserve1_14 "平台预留报文";
CM_ SG_ 2148958110 M2S_CMD6_Reserve2_14 "平台预留报文";
CM_ SG_ 2148958110 M2S_CMD6_Reserve3_14 "平台预留报文";
CM_ SG_ 2148958110 M2S_CMD6_Reserve4_14 "平台预留报文";
CM_ SG_ 2148958110 M2S_CMD6_Reserve5_14 "平台预留报文";
CM_ SG_ 2148958110 M2S_CMD6_Reserve6_14 "平台预留报文";
CM_ SG_ 2148958110 M2S_CMD6_Reserve7_14 "平台预留报文";
CM_ SG_ 2148958110 M2S_CMD6_Reserve8_14 "平台预留报文";
CM_ SG_ 2148958111 M2S_CMD6_Reserve1_15 "平台预留报文";
CM_ SG_ 2148958111 M2S_CMD6_Reserve2_15 "平台预留报文";
CM_ SG_ 2148958111 M2S_CMD6_Reserve3_15 "平台预留报文";
CM_ SG_ 2148958111 M2S_CMD6_Reserve4_15 "平台预留报文";
CM_ SG_ 2148958111 M2S_CMD6_Reserve5_15 "平台预留报文";
CM_ SG_ 2148958111 M2S_CMD6_Reserve6_15 "平台预留报文";
CM_ SG_ 2148958111 M2S_CMD6_Reserve7_15 "平台预留报文";
CM_ SG_ 2148958111 M2S_CMD6_Reserve8_15 "平台预留报文";
CM_ SG_ 2148958112 M2S_CMD6_Reserve1_16 "平台预留报文";
CM_ SG_ 2148958112 M2S_CMD6_Reserve2_16 "平台预留报文";
CM_ SG_ 2148958112 M2S_CMD6_Reserve3_16 "平台预留报文";
CM_ SG_ 2148958112 M2S_CMD6_Reserve4_16 "平台预留报文";
CM_ SG_ 2148958112 M2S_CMD6_Reserve5_16 "平台预留报文";
CM_ SG_ 2148958112 M2S_CMD6_Reserve6_16 "平台预留报文";
CM_ SG_ 2148958112 M2S_CMD6_Reserve7_16 "平台预留报文";
CM_ SG_ 2148958112 M2S_CMD6_Reserve8_16 "平台预留报文";
CM_ SG_ 2148958113 M2S_CMD6_Reserve1_17 "平台预留报文";
CM_ SG_ 2148958113 M2S_CMD6_Reserve2_17 "平台预留报文";
CM_ SG_ 2148958113 M2S_CMD6_Reserve3_17 "平台预留报文";
CM_ SG_ 2148958113 M2S_CMD6_Reserve4_17 "平台预留报文";
CM_ SG_ 2148958113 M2S_CMD6_Reserve5_17 "平台预留报文";
CM_ SG_ 2148958113 M2S_CMD6_Reserve6_17 "平台预留报文";
CM_ SG_ 2148958113 M2S_CMD6_Reserve7_17 "平台预留报文";
CM_ SG_ 2148958113 M2S_CMD6_Reserve8_17 "平台预留报文";
CM_ SG_ 2148958114 M2S_CMD6_Reserve1_18 "平台预留报文";
CM_ SG_ 2148958114 M2S_CMD6_Reserve2_18 "平台预留报文";
CM_ SG_ 2148958114 M2S_CMD6_Reserve3_18 "平台预留报文";
CM_ SG_ 2148958114 M2S_CMD6_Reserve4_18 "平台预留报文";
CM_ SG_ 2148958114 M2S_CMD6_Reserve5_18 "平台预留报文";
CM_ SG_ 2148958114 M2S_CMD6_Reserve6_18 "平台预留报文";
CM_ SG_ 2148958114 M2S_CMD6_Reserve7_18 "平台预留报文";
CM_ SG_ 2148958114 M2S_CMD6_Reserve8_18 "平台预留报文";
CM_ SG_ 2148958115 M2S_CMD6_Reserve1_19 "平台预留报文";
CM_ SG_ 2148958115 M2S_CMD6_Reserve2_19 "平台预留报文";
CM_ SG_ 2148958115 M2S_CMD6_Reserve3_19 "平台预留报文";
CM_ SG_ 2148958115 M2S_CMD6_Reserve4_19 "平台预留报文";
CM_ SG_ 2148958115 M2S_CMD6_Reserve5_19 "平台预留报文";
CM_ SG_ 2148958115 M2S_CMD6_Reserve6_19 "平台预留报文";
CM_ SG_ 2148958115 M2S_CMD6_Reserve7_19 "平台预留报文";
CM_ SG_ 2148958115 M2S_CMD6_Reserve8_19 "平台预留报文";
CM_ SG_ 2148958116 M2S_CMD6_Reserve1_20 "平台预留报文";
CM_ SG_ 2148958116 M2S_CMD6_Reserve2_20 "平台预留报文";
CM_ SG_ 2148958116 M2S_CMD6_Reserve3_20 "平台预留报文";
CM_ SG_ 2148958116 M2S_CMD6_Reserve4_20 "平台预留报文";
CM_ SG_ 2148958116 M2S_CMD6_Reserve5_20 "平台预留报文";
CM_ SG_ 2148958116 M2S_CMD6_Reserve6_20 "平台预留报文";
CM_ SG_ 2148958116 M2S_CMD6_Reserve7_20 "平台预留报文";
CM_ SG_ 2148958116 M2S_CMD6_Reserve8_20 "平台预留报文";
CM_ SG_ 2148958117 M2S_CMD6_Reserve1_21 "平台预留报文";
CM_ SG_ 2148958117 M2S_CMD6_Reserve2_21 "平台预留报文";
CM_ SG_ 2148958117 M2S_CMD6_Reserve3_21 "平台预留报文";
CM_ SG_ 2148958117 M2S_CMD6_Reserve4_21 "平台预留报文";
CM_ SG_ 2148958117 M2S_CMD6_Reserve5_21 "平台预留报文";
CM_ SG_ 2148958117 M2S_CMD6_Reserve6_21 "平台预留报文";
CM_ SG_ 2148958117 M2S_CMD6_Reserve7_21 "平台预留报文";
CM_ SG_ 2148958117 M2S_CMD6_Reserve8_21 "平台预留报文";
CM_ SG_ 2148958118 M2S_CMD6_Reserve1_22 "平台预留报文";
CM_ SG_ 2148958118 M2S_CMD6_Reserve2_22 "平台预留报文";
CM_ SG_ 2148958118 M2S_CMD6_Reserve3_22 "平台预留报文";
CM_ SG_ 2148958118 M2S_CMD6_Reserve4_22 "平台预留报文";
CM_ SG_ 2148958118 M2S_CMD6_Reserve5_22 "平台预留报文";
CM_ SG_ 2148958118 M2S_CMD6_Reserve6_22 "平台预留报文";
CM_ SG_ 2148958118 M2S_CMD6_Reserve7_22 "平台预留报文";
CM_ SG_ 2148958118 M2S_CMD6_Reserve8_22 "平台预留报文";
CM_ SG_ 2148958119 M2S_CMD6_Reserve1_23 "平台预留报文";
CM_ SG_ 2148958119 M2S_CMD6_Reserve2_23 "平台预留报文";
CM_ SG_ 2148958119 M2S_CMD6_Reserve3_23 "平台预留报文";
CM_ SG_ 2148958119 M2S_CMD6_Reserve4_23 "平台预留报文";
CM_ SG_ 2148958119 M2S_CMD6_Reserve5_23 "平台预留报文";
CM_ SG_ 2148958119 M2S_CMD6_Reserve6_23 "平台预留报文";
CM_ SG_ 2148958119 M2S_CMD6_Reserve7_23 "平台预留报文";
CM_ SG_ 2148958119 M2S_CMD6_Reserve8_23 "平台预留报文";
CM_ SG_ 2148958120 M2S_CMD6_Reserve1_24 "平台预留报文";
CM_ SG_ 2148958120 M2S_CMD6_Reserve2_24 "平台预留报文";
CM_ SG_ 2148958120 M2S_CMD6_Reserve3_24 "平台预留报文";
CM_ SG_ 2148958120 M2S_CMD6_Reserve4_24 "平台预留报文";
CM_ SG_ 2148958120 M2S_CMD6_Reserve5_24 "平台预留报文";
CM_ SG_ 2148958120 M2S_CMD6_Reserve6_24 "平台预留报文";
CM_ SG_ 2148958120 M2S_CMD6_Reserve7_24 "平台预留报文";
CM_ SG_ 2148958120 M2S_CMD6_Reserve8_24 "平台预留报文";
CM_ SG_ 2148958121 M2S_CMD6_Reserve1_25 "平台预留报文";
CM_ SG_ 2148958121 M2S_CMD6_Reserve2_25 "平台预留报文";
CM_ SG_ 2148958121 M2S_CMD6_Reserve3_25 "平台预留报文";
CM_ SG_ 2148958121 M2S_CMD6_Reserve4_25 "平台预留报文";
CM_ SG_ 2148958121 M2S_CMD6_Reserve5_25 "平台预留报文";
CM_ SG_ 2148958121 M2S_CMD6_Reserve6_25 "平台预留报文";
CM_ SG_ 2148958121 M2S_CMD6_Reserve7_25 "平台预留报文";
CM_ SG_ 2148958121 M2S_CMD6_Reserve8_25 "平台预留报文";
CM_ SG_ 2148958122 M2S_CMD6_Reserve1_26 "平台预留报文";
CM_ SG_ 2148958122 M2S_CMD6_Reserve2_26 "平台预留报文";
CM_ SG_ 2148958122 M2S_CMD6_Reserve3_26 "平台预留报文";
CM_ SG_ 2148958122 M2S_CMD6_Reserve4_26 "平台预留报文";
CM_ SG_ 2148958122 M2S_CMD6_Reserve5_26 "平台预留报文";
CM_ SG_ 2148958122 M2S_CMD6_Reserve6_26 "平台预留报文";
CM_ SG_ 2148958122 M2S_CMD6_Reserve7_26 "平台预留报文";
CM_ SG_ 2148958122 M2S_CMD6_Reserve8_26 "平台预留报文";
CM_ SG_ 2148958123 M2S_CMD6_Reserve1_27 "平台预留报文";
CM_ SG_ 2148958123 M2S_CMD6_Reserve2_27 "平台预留报文";
CM_ SG_ 2148958123 M2S_CMD6_Reserve3_27 "平台预留报文";
CM_ SG_ 2148958123 M2S_CMD6_Reserve4_27 "平台预留报文";
CM_ SG_ 2148958123 M2S_CMD6_Reserve5_27 "平台预留报文";
CM_ SG_ 2148958123 M2S_CMD6_Reserve6_27 "平台预留报文";
CM_ SG_ 2148958123 M2S_CMD6_Reserve7_27 "平台预留报文";
CM_ SG_ 2148958123 M2S_CMD6_Reserve8_27 "平台预留报文";
CM_ SG_ 2148958124 M2S_CMD6_Reserve1_28 "平台预留报文";
CM_ SG_ 2148958124 M2S_CMD6_Reserve2_28 "平台预留报文";
CM_ SG_ 2148958124 M2S_CMD6_Reserve3_28 "平台预留报文";
CM_ SG_ 2148958124 M2S_CMD6_Reserve4_28 "平台预留报文";
CM_ SG_ 2148958124 M2S_CMD6_Reserve5_28 "平台预留报文";
CM_ SG_ 2148958124 M2S_CMD6_Reserve6_28 "平台预留报文";
CM_ SG_ 2148958124 M2S_CMD6_Reserve7_28 "平台预留报文";
CM_ SG_ 2148958124 M2S_CMD6_Reserve8_28 "平台预留报文";
CM_ SG_ 2148958125 M2S_CMD6_Reserve1_29 "平台预留报文";
CM_ SG_ 2148958125 M2S_CMD6_Reserve2_29 "平台预留报文";
CM_ SG_ 2148958125 M2S_CMD6_Reserve3_29 "平台预留报文";
CM_ SG_ 2148958125 M2S_CMD6_Reserve4_29 "平台预留报文";
CM_ SG_ 2148958125 M2S_CMD6_Reserve5_29 "平台预留报文";
CM_ SG_ 2148958125 M2S_CMD6_Reserve6_29 "平台预留报文";
CM_ SG_ 2148958125 M2S_CMD6_Reserve7_29 "平台预留报文";
CM_ SG_ 2148958125 M2S_CMD6_Reserve8_29 "平台预留报文";
CM_ SG_ 2148958126 M2S_CMD6_Reserve1_30 "平台预留报文";
CM_ SG_ 2148958126 M2S_CMD6_Reserve2_30 "平台预留报文";
CM_ SG_ 2148958126 M2S_CMD6_Reserve3_30 "平台预留报文";
CM_ SG_ 2148958126 M2S_CMD6_Reserve4_30 "平台预留报文";
CM_ SG_ 2148958126 M2S_CMD6_Reserve5_30 "平台预留报文";
CM_ SG_ 2148958126 M2S_CMD6_Reserve6_30 "平台预留报文";
CM_ SG_ 2148958126 M2S_CMD6_Reserve7_30 "平台预留报文";
CM_ SG_ 2148958126 M2S_CMD6_Reserve8_30 "平台预留报文";
CM_ SG_ 2148958127 M2S_CMD6_Reserve1_31 "平台预留报文";
CM_ SG_ 2148958127 M2S_CMD6_Reserve2_31 "平台预留报文";
CM_ SG_ 2148958127 M2S_CMD6_Reserve3_31 "平台预留报文";
CM_ SG_ 2148958127 M2S_CMD6_Reserve4_31 "平台预留报文";
CM_ SG_ 2148958127 M2S_CMD6_Reserve5_31 "平台预留报文";
CM_ SG_ 2148958127 M2S_CMD6_Reserve6_31 "平台预留报文";
CM_ SG_ 2148958127 M2S_CMD6_Reserve7_31 "平台预留报文";
CM_ SG_ 2148958127 M2S_CMD6_Reserve8_31 "平台预留报文";
CM_ SG_ 2154921873 M2S_CMD1_CUS_Reserve1_01 "客户预留报文";
CM_ SG_ 2154921873 M2S_CMD1_CUS_Reserve2_01 "客户预留报文";
CM_ SG_ 2154921873 M2S_CMD1_CUS_Reserve3_01 "客户预留报文";
CM_ SG_ 2154921873 M2S_CMD1_CUS_Reserve4_01 "客户预留报文";
CM_ SG_ 2154921873 M2S_CMD1_CUS_Reserve5_01 "客户预留报文";
CM_ SG_ 2154921873 M2S_CMD1_CUS_Reserve6_01 "客户预留报文";
CM_ SG_ 2154921873 M2S_CMD1_CUS_Reserve7_01 "客户预留报文";
CM_ SG_ 2154921873 M2S_CMD1_CUS_Reserve8_01 "客户预留报文";
CM_ SG_ 2154921874 M2S_CMD1_CUS_Reserve1_02 "客户预留报文";
CM_ SG_ 2154921874 M2S_CMD1_CUS_Reserve2_02 "客户预留报文";
CM_ SG_ 2154921874 M2S_CMD1_CUS_Reserve3_02 "客户预留报文";
CM_ SG_ 2154921874 M2S_CMD1_CUS_Reserve4_02 "客户预留报文";
CM_ SG_ 2154921874 M2S_CMD1_CUS_Reserve5_02 "客户预留报文";
CM_ SG_ 2154921874 M2S_CMD1_CUS_Reserve6_02 "客户预留报文";
CM_ SG_ 2154921874 M2S_CMD1_CUS_Reserve7_02 "客户预留报文";
CM_ SG_ 2154921874 M2S_CMD1_CUS_Reserve8_02 "客户预留报文";
CM_ SG_ 2154921875 M2S_CMD1_CUS_Reserve1_03 "客户预留报文";
CM_ SG_ 2154921875 M2S_CMD1_CUS_Reserve2_03 "客户预留报文";
CM_ SG_ 2154921875 M2S_CMD1_CUS_Reserve3_03 "客户预留报文";
CM_ SG_ 2154921875 M2S_CMD1_CUS_Reserve4_03 "客户预留报文";
CM_ SG_ 2154921875 M2S_CMD1_CUS_Reserve5_03 "客户预留报文";
CM_ SG_ 2154921875 M2S_CMD1_CUS_Reserve6_03 "客户预留报文";
CM_ SG_ 2154921875 M2S_CMD1_CUS_Reserve7_03 "客户预留报文";
CM_ SG_ 2154921875 M2S_CMD1_CUS_Reserve8_03 "客户预留报文";
CM_ SG_ 2154921876 M2S_CMD1_CUS_Reserve1_04 "客户预留报文";
CM_ SG_ 2154921876 M2S_CMD1_CUS_Reserve2_04 "客户预留报文";
CM_ SG_ 2154921876 M2S_CMD1_CUS_Reserve3_04 "客户预留报文";
CM_ SG_ 2154921876 M2S_CMD1_CUS_Reserve4_04 "客户预留报文";
CM_ SG_ 2154921876 M2S_CMD1_CUS_Reserve5_04 "客户预留报文";
CM_ SG_ 2154921876 M2S_CMD1_CUS_Reserve6_04 "客户预留报文";
CM_ SG_ 2154921876 M2S_CMD1_CUS_Reserve7_04 "客户预留报文";
CM_ SG_ 2154921876 M2S_CMD1_CUS_Reserve8_04 "客户预留报文";
CM_ SG_ 2154921877 M2S_CMD1_CUS_Reserve1_05 "客户预留报文";
CM_ SG_ 2154921877 M2S_CMD1_CUS_Reserve2_05 "客户预留报文";
CM_ SG_ 2154921877 M2S_CMD1_CUS_Reserve3_05 "客户预留报文";
CM_ SG_ 2154921877 M2S_CMD1_CUS_Reserve4_05 "客户预留报文";
CM_ SG_ 2154921877 M2S_CMD1_CUS_Reserve5_05 "客户预留报文";
CM_ SG_ 2154921877 M2S_CMD1_CUS_Reserve6_05 "客户预留报文";
CM_ SG_ 2154921877 M2S_CMD1_CUS_Reserve7_05 "客户预留报文";
CM_ SG_ 2154921877 M2S_CMD1_CUS_Reserve8_05 "客户预留报文";
CM_ SG_ 2154921878 M2S_CMD1_CUS_Reserve1_06 "客户预留报文";
CM_ SG_ 2154921878 M2S_CMD1_CUS_Reserve2_06 "客户预留报文";
CM_ SG_ 2154921878 M2S_CMD1_CUS_Reserve3_06 "客户预留报文";
CM_ SG_ 2154921878 M2S_CMD1_CUS_Reserve4_06 "客户预留报文";
CM_ SG_ 2154921878 M2S_CMD1_CUS_Reserve5_06 "客户预留报文";
CM_ SG_ 2154921878 M2S_CMD1_CUS_Reserve6_06 "客户预留报文";
CM_ SG_ 2154921878 M2S_CMD1_CUS_Reserve7_06 "客户预留报文";
CM_ SG_ 2154921878 M2S_CMD1_CUS_Reserve8_06 "客户预留报文";
CM_ SG_ 2154921879 M2S_CMD1_CUS_Reserve1_07 "客户预留报文";
CM_ SG_ 2154921879 M2S_CMD1_CUS_Reserve2_07 "客户预留报文";
CM_ SG_ 2154921879 M2S_CMD1_CUS_Reserve3_07 "客户预留报文";
CM_ SG_ 2154921879 M2S_CMD1_CUS_Reserve4_07 "客户预留报文";
CM_ SG_ 2154921879 M2S_CMD1_CUS_Reserve5_07 "客户预留报文";
CM_ SG_ 2154921879 M2S_CMD1_CUS_Reserve6_07 "客户预留报文";
CM_ SG_ 2154921879 M2S_CMD1_CUS_Reserve7_07 "客户预留报文";
CM_ SG_ 2154921879 M2S_CMD1_CUS_Reserve8_07 "客户预留报文";
CM_ SG_ 2154921880 M2S_CMD1_CUS_Reserve1_08 "客户预留报文";
CM_ SG_ 2154921880 M2S_CMD1_CUS_Reserve2_08 "客户预留报文";
CM_ SG_ 2154921880 M2S_CMD1_CUS_Reserve3_08 "客户预留报文";
CM_ SG_ 2154921880 M2S_CMD1_CUS_Reserve4_08 "客户预留报文";
CM_ SG_ 2154921880 M2S_CMD1_CUS_Reserve5_08 "客户预留报文";
CM_ SG_ 2154921880 M2S_CMD1_CUS_Reserve6_08 "客户预留报文";
CM_ SG_ 2154921880 M2S_CMD1_CUS_Reserve7_08 "客户预留报文";
CM_ SG_ 2154921880 M2S_CMD1_CUS_Reserve8_08 "客户预留报文";
CM_ SG_ 2154921881 M2S_CMD1_CUS_Reserve1_09 "客户预留报文";
CM_ SG_ 2154921881 M2S_CMD1_CUS_Reserve2_09 "客户预留报文";
CM_ SG_ 2154921881 M2S_CMD1_CUS_Reserve3_09 "客户预留报文";
CM_ SG_ 2154921881 M2S_CMD1_CUS_Reserve4_09 "客户预留报文";
CM_ SG_ 2154921881 M2S_CMD1_CUS_Reserve5_09 "客户预留报文";
CM_ SG_ 2154921881 M2S_CMD1_CUS_Reserve6_09 "客户预留报文";
CM_ SG_ 2154921881 M2S_CMD1_CUS_Reserve7_09 "客户预留报文";
CM_ SG_ 2154921881 M2S_CMD1_CUS_Reserve8_09 "客户预留报文";
CM_ SG_ 2154921882 M2S_CMD1_CUS_Reserve1_10 "客户预留报文";
CM_ SG_ 2154921882 M2S_CMD1_CUS_Reserve2_10 "客户预留报文";
CM_ SG_ 2154921882 M2S_CMD1_CUS_Reserve3_10 "客户预留报文";
CM_ SG_ 2154921882 M2S_CMD1_CUS_Reserve4_10 "客户预留报文";
CM_ SG_ 2154921882 M2S_CMD1_CUS_Reserve5_10 "客户预留报文";
CM_ SG_ 2154921882 M2S_CMD1_CUS_Reserve6_10 "客户预留报文";
CM_ SG_ 2154921882 M2S_CMD1_CUS_Reserve7_10 "客户预留报文";
CM_ SG_ 2154921882 M2S_CMD1_CUS_Reserve8_10 "客户预留报文";
CM_ SG_ 2154921883 M2S_CMD1_CUS_Reserve1_11 "客户预留报文";
CM_ SG_ 2154921883 M2S_CMD1_CUS_Reserve2_11 "客户预留报文";
CM_ SG_ 2154921883 M2S_CMD1_CUS_Reserve3_11 "客户预留报文";
CM_ SG_ 2154921883 M2S_CMD1_CUS_Reserve4_11 "客户预留报文";
CM_ SG_ 2154921883 M2S_CMD1_CUS_Reserve5_11 "客户预留报文";
CM_ SG_ 2154921883 M2S_CMD1_CUS_Reserve6_11 "客户预留报文";
CM_ SG_ 2154921883 M2S_CMD1_CUS_Reserve7_11 "客户预留报文";
CM_ SG_ 2154921883 M2S_CMD1_CUS_Reserve8_11 "客户预留报文";
CM_ SG_ 2154921884 M2S_CMD1_CUS_Reserve1_12 "客户预留报文";
CM_ SG_ 2154921884 M2S_CMD1_CUS_Reserve2_12 "客户预留报文";
CM_ SG_ 2154921884 M2S_CMD1_CUS_Reserve3_12 "客户预留报文";
CM_ SG_ 2154921884 M2S_CMD1_CUS_Reserve4_12 "客户预留报文";
CM_ SG_ 2154921884 M2S_CMD1_CUS_Reserve5_12 "客户预留报文";
CM_ SG_ 2154921884 M2S_CMD1_CUS_Reserve6_12 "客户预留报文";
CM_ SG_ 2154921884 M2S_CMD1_CUS_Reserve7_12 "客户预留报文";
CM_ SG_ 2154921884 M2S_CMD1_CUS_Reserve8_12 "客户预留报文";
CM_ SG_ 2154921885 M2S_CMD1_CUS_Reserve1_13 "客户预留报文";
CM_ SG_ 2154921885 M2S_CMD1_CUS_Reserve2_13 "客户预留报文";
CM_ SG_ 2154921885 M2S_CMD1_CUS_Reserve3_13 "客户预留报文";
CM_ SG_ 2154921885 M2S_CMD1_CUS_Reserve4_13 "客户预留报文";
CM_ SG_ 2154921885 M2S_CMD1_CUS_Reserve5_13 "客户预留报文";
CM_ SG_ 2154921885 M2S_CMD1_CUS_Reserve6_13 "客户预留报文";
CM_ SG_ 2154921885 M2S_CMD1_CUS_Reserve7_13 "客户预留报文";
CM_ SG_ 2154921885 M2S_CMD1_CUS_Reserve8_13 "客户预留报文";
CM_ SG_ 2154921886 M2S_CMD1_CUS_Reserve1_14 "客户预留报文";
CM_ SG_ 2154921886 M2S_CMD1_CUS_Reserve2_14 "客户预留报文";
CM_ SG_ 2154921886 M2S_CMD1_CUS_Reserve3_14 "客户预留报文";
CM_ SG_ 2154921886 M2S_CMD1_CUS_Reserve4_14 "客户预留报文";
CM_ SG_ 2154921886 M2S_CMD1_CUS_Reserve5_14 "客户预留报文";
CM_ SG_ 2154921886 M2S_CMD1_CUS_Reserve6_14 "客户预留报文";
CM_ SG_ 2154921886 M2S_CMD1_CUS_Reserve7_14 "客户预留报文";
CM_ SG_ 2154921886 M2S_CMD1_CUS_Reserve8_14 "客户预留报文";
CM_ SG_ 2154921887 M2S_CMD1_CUS_Reserve1_15 "客户预留报文";
CM_ SG_ 2154921887 M2S_CMD1_CUS_Reserve2_15 "客户预留报文";
CM_ SG_ 2154921887 M2S_CMD1_CUS_Reserve3_15 "客户预留报文";
CM_ SG_ 2154921887 M2S_CMD1_CUS_Reserve4_15 "客户预留报文";
CM_ SG_ 2154921887 M2S_CMD1_CUS_Reserve5_15 "客户预留报文";
CM_ SG_ 2154921887 M2S_CMD1_CUS_Reserve6_15 "客户预留报文";
CM_ SG_ 2154921887 M2S_CMD1_CUS_Reserve7_15 "客户预留报文";
CM_ SG_ 2154921887 M2S_CMD1_CUS_Reserve8_15 "客户预留报文";
CM_ SG_ 2154921888 M2S_CMD1_CUS_Reserve1_16 "客户预留报文";
CM_ SG_ 2154921888 M2S_CMD1_CUS_Reserve2_16 "客户预留报文";
CM_ SG_ 2154921888 M2S_CMD1_CUS_Reserve3_16 "客户预留报文";
CM_ SG_ 2154921888 M2S_CMD1_CUS_Reserve4_16 "客户预留报文";
CM_ SG_ 2154921888 M2S_CMD1_CUS_Reserve5_16 "客户预留报文";
CM_ SG_ 2154921888 M2S_CMD1_CUS_Reserve6_16 "客户预留报文";
CM_ SG_ 2154921888 M2S_CMD1_CUS_Reserve7_16 "客户预留报文";
CM_ SG_ 2154921888 M2S_CMD1_CUS_Reserve8_16 "客户预留报文";
CM_ SG_ 2154921889 M2S_CMD1_CUS_Reserve1_17 "客户预留报文";
CM_ SG_ 2154921889 M2S_CMD1_CUS_Reserve2_17 "客户预留报文";
CM_ SG_ 2154921889 M2S_CMD1_CUS_Reserve3_17 "客户预留报文";
CM_ SG_ 2154921889 M2S_CMD1_CUS_Reserve4_17 "客户预留报文";
CM_ SG_ 2154921889 M2S_CMD1_CUS_Reserve5_17 "客户预留报文";
CM_ SG_ 2154921889 M2S_CMD1_CUS_Reserve6_17 "客户预留报文";
CM_ SG_ 2154921889 M2S_CMD1_CUS_Reserve7_17 "客户预留报文";
CM_ SG_ 2154921889 M2S_CMD1_CUS_Reserve8_17 "客户预留报文";
CM_ SG_ 2154921890 M2S_CMD1_CUS_Reserve1_18 "客户预留报文";
CM_ SG_ 2154921890 M2S_CMD1_CUS_Reserve2_18 "客户预留报文";
CM_ SG_ 2154921890 M2S_CMD1_CUS_Reserve3_18 "客户预留报文";
CM_ SG_ 2154921890 M2S_CMD1_CUS_Reserve4_18 "客户预留报文";
CM_ SG_ 2154921890 M2S_CMD1_CUS_Reserve5_18 "客户预留报文";
CM_ SG_ 2154921890 M2S_CMD1_CUS_Reserve6_18 "客户预留报文";
CM_ SG_ 2154921890 M2S_CMD1_CUS_Reserve7_18 "客户预留报文";
CM_ SG_ 2154921890 M2S_CMD1_CUS_Reserve8_18 "客户预留报文";
CM_ SG_ 2154921891 M2S_CMD1_CUS_Reserve1_19 "客户预留报文";
CM_ SG_ 2154921891 M2S_CMD1_CUS_Reserve2_19 "客户预留报文";
CM_ SG_ 2154921891 M2S_CMD1_CUS_Reserve3_19 "客户预留报文";
CM_ SG_ 2154921891 M2S_CMD1_CUS_Reserve4_19 "客户预留报文";
CM_ SG_ 2154921891 M2S_CMD1_CUS_Reserve5_19 "客户预留报文";
CM_ SG_ 2154921891 M2S_CMD1_CUS_Reserve6_19 "客户预留报文";
CM_ SG_ 2154921891 M2S_CMD1_CUS_Reserve7_19 "客户预留报文";
CM_ SG_ 2154921891 M2S_CMD1_CUS_Reserve8_19 "客户预留报文";
CM_ SG_ 2154921892 M2S_CMD1_CUS_Reserve1_20 "客户预留报文";
CM_ SG_ 2154921892 M2S_CMD1_CUS_Reserve2_20 "客户预留报文";
CM_ SG_ 2154921892 M2S_CMD1_CUS_Reserve3_20 "客户预留报文";
CM_ SG_ 2154921892 M2S_CMD1_CUS_Reserve4_20 "客户预留报文";
CM_ SG_ 2154921892 M2S_CMD1_CUS_Reserve5_20 "客户预留报文";
CM_ SG_ 2154921892 M2S_CMD1_CUS_Reserve6_20 "客户预留报文";
CM_ SG_ 2154921892 M2S_CMD1_CUS_Reserve7_20 "客户预留报文";
CM_ SG_ 2154921892 M2S_CMD1_CUS_Reserve8_20 "客户预留报文";
CM_ SG_ 2154921893 M2S_CMD1_CUS_Reserve1_21 "客户预留报文";
CM_ SG_ 2154921893 M2S_CMD1_CUS_Reserve2_21 "客户预留报文";
CM_ SG_ 2154921893 M2S_CMD1_CUS_Reserve3_21 "客户预留报文";
CM_ SG_ 2154921893 M2S_CMD1_CUS_Reserve4_21 "客户预留报文";
CM_ SG_ 2154921893 M2S_CMD1_CUS_Reserve5_21 "客户预留报文";
CM_ SG_ 2154921893 M2S_CMD1_CUS_Reserve6_21 "客户预留报文";
CM_ SG_ 2154921893 M2S_CMD1_CUS_Reserve7_21 "客户预留报文";
CM_ SG_ 2154921893 M2S_CMD1_CUS_Reserve8_21 "客户预留报文";
CM_ SG_ 2154921894 M2S_CMD1_CUS_Reserve1_22 "客户预留报文";
CM_ SG_ 2154921894 M2S_CMD1_CUS_Reserve2_22 "客户预留报文";
CM_ SG_ 2154921894 M2S_CMD1_CUS_Reserve3_22 "客户预留报文";
CM_ SG_ 2154921894 M2S_CMD1_CUS_Reserve4_22 "客户预留报文";
CM_ SG_ 2154921894 M2S_CMD1_CUS_Reserve5_22 "客户预留报文";
CM_ SG_ 2154921894 M2S_CMD1_CUS_Reserve6_22 "客户预留报文";
CM_ SG_ 2154921894 M2S_CMD1_CUS_Reserve7_22 "客户预留报文";
CM_ SG_ 2154921894 M2S_CMD1_CUS_Reserve8_22 "客户预留报文";
CM_ SG_ 2154921895 M2S_CMD1_CUS_Reserve1_23 "客户预留报文";
CM_ SG_ 2154921895 M2S_CMD1_CUS_Reserve2_23 "客户预留报文";
CM_ SG_ 2154921895 M2S_CMD1_CUS_Reserve3_23 "客户预留报文";
CM_ SG_ 2154921895 M2S_CMD1_CUS_Reserve4_23 "客户预留报文";
CM_ SG_ 2154921895 M2S_CMD1_CUS_Reserve5_23 "客户预留报文";
CM_ SG_ 2154921895 M2S_CMD1_CUS_Reserve6_23 "客户预留报文";
CM_ SG_ 2154921895 M2S_CMD1_CUS_Reserve7_23 "客户预留报文";
CM_ SG_ 2154921895 M2S_CMD1_CUS_Reserve8_23 "客户预留报文";
CM_ SG_ 2154921896 M2S_CMD1_CUS_Reserve1_24 "客户预留报文";
CM_ SG_ 2154921896 M2S_CMD1_CUS_Reserve2_24 "客户预留报文";
CM_ SG_ 2154921896 M2S_CMD1_CUS_Reserve3_24 "客户预留报文";
CM_ SG_ 2154921896 M2S_CMD1_CUS_Reserve4_24 "客户预留报文";
CM_ SG_ 2154921896 M2S_CMD1_CUS_Reserve5_24 "客户预留报文";
CM_ SG_ 2154921896 M2S_CMD1_CUS_Reserve6_24 "客户预留报文";
CM_ SG_ 2154921896 M2S_CMD1_CUS_Reserve7_24 "客户预留报文";
CM_ SG_ 2154921896 M2S_CMD1_CUS_Reserve8_24 "客户预留报文";
CM_ SG_ 2154921897 M2S_CMD1_CUS_Reserve1_25 "客户预留报文";
CM_ SG_ 2154921897 M2S_CMD1_CUS_Reserve2_25 "客户预留报文";
CM_ SG_ 2154921897 M2S_CMD1_CUS_Reserve3_25 "客户预留报文";
CM_ SG_ 2154921897 M2S_CMD1_CUS_Reserve4_25 "客户预留报文";
CM_ SG_ 2154921897 M2S_CMD1_CUS_Reserve5_25 "客户预留报文";
CM_ SG_ 2154921897 M2S_CMD1_CUS_Reserve6_25 "客户预留报文";
CM_ SG_ 2154921897 M2S_CMD1_CUS_Reserve7_25 "客户预留报文";
CM_ SG_ 2154921897 M2S_CMD1_CUS_Reserve8_25 "客户预留报文";
CM_ SG_ 2154921898 M2S_CMD1_CUS_Reserve1_26 "客户预留报文";
CM_ SG_ 2154921898 M2S_CMD1_CUS_Reserve2_26 "客户预留报文";
CM_ SG_ 2154921898 M2S_CMD1_CUS_Reserve3_26 "客户预留报文";
CM_ SG_ 2154921898 M2S_CMD1_CUS_Reserve4_26 "客户预留报文";
CM_ SG_ 2154921898 M2S_CMD1_CUS_Reserve5_26 "客户预留报文";
CM_ SG_ 2154921898 M2S_CMD1_CUS_Reserve6_26 "客户预留报文";
CM_ SG_ 2154921898 M2S_CMD1_CUS_Reserve7_26 "客户预留报文";
CM_ SG_ 2154921898 M2S_CMD1_CUS_Reserve8_26 "客户预留报文";
CM_ SG_ 2154921899 M2S_CMD1_CUS_Reserve1_27 "客户预留报文";
CM_ SG_ 2154921899 M2S_CMD1_CUS_Reserve2_27 "客户预留报文";
CM_ SG_ 2154921899 M2S_CMD1_CUS_Reserve3_27 "客户预留报文";
CM_ SG_ 2154921899 M2S_CMD1_CUS_Reserve4_27 "客户预留报文";
CM_ SG_ 2154921899 M2S_CMD1_CUS_Reserve5_27 "客户预留报文";
CM_ SG_ 2154921899 M2S_CMD1_CUS_Reserve6_27 "客户预留报文";
CM_ SG_ 2154921899 M2S_CMD1_CUS_Reserve7_27 "客户预留报文";
CM_ SG_ 2154921899 M2S_CMD1_CUS_Reserve8_27 "客户预留报文";
CM_ SG_ 2154921900 M2S_CMD1_CUS_Reserve1_28 "客户预留报文";
CM_ SG_ 2154921900 M2S_CMD1_CUS_Reserve2_28 "客户预留报文";
CM_ SG_ 2154921900 M2S_CMD1_CUS_Reserve3_28 "客户预留报文";
CM_ SG_ 2154921900 M2S_CMD1_CUS_Reserve4_28 "客户预留报文";
CM_ SG_ 2154921900 M2S_CMD1_CUS_Reserve5_28 "客户预留报文";
CM_ SG_ 2154921900 M2S_CMD1_CUS_Reserve6_28 "客户预留报文";
CM_ SG_ 2154921900 M2S_CMD1_CUS_Reserve7_28 "客户预留报文";
CM_ SG_ 2154921900 M2S_CMD1_CUS_Reserve8_28 "客户预留报文";
CM_ SG_ 2154921901 M2S_CMD1_CUS_Reserve1_29 "客户预留报文";
CM_ SG_ 2154921901 M2S_CMD1_CUS_Reserve2_29 "客户预留报文";
CM_ SG_ 2154921901 M2S_CMD1_CUS_Reserve3_29 "客户预留报文";
CM_ SG_ 2154921901 M2S_CMD1_CUS_Reserve4_29 "客户预留报文";
CM_ SG_ 2154921901 M2S_CMD1_CUS_Reserve5_29 "客户预留报文";
CM_ SG_ 2154921901 M2S_CMD1_CUS_Reserve6_29 "客户预留报文";
CM_ SG_ 2154921901 M2S_CMD1_CUS_Reserve7_29 "客户预留报文";
CM_ SG_ 2154921901 M2S_CMD1_CUS_Reserve8_29 "客户预留报文";
CM_ SG_ 2154921902 M2S_CMD1_CUS_Reserve1_30 "客户预留报文";
CM_ SG_ 2154921902 M2S_CMD1_CUS_Reserve2_30 "客户预留报文";
CM_ SG_ 2154921902 M2S_CMD1_CUS_Reserve3_30 "客户预留报文";
CM_ SG_ 2154921902 M2S_CMD1_CUS_Reserve4_30 "客户预留报文";
CM_ SG_ 2154921902 M2S_CMD1_CUS_Reserve5_30 "客户预留报文";
CM_ SG_ 2154921902 M2S_CMD1_CUS_Reserve6_30 "客户预留报文";
CM_ SG_ 2154921902 M2S_CMD1_CUS_Reserve7_30 "客户预留报文";
CM_ SG_ 2154921902 M2S_CMD1_CUS_Reserve8_30 "客户预留报文";
CM_ SG_ 2154921903 M2S_CMD1_CUS_Reserve1_31 "客户预留报文";
CM_ SG_ 2154921903 M2S_CMD1_CUS_Reserve2_31 "客户预留报文";
CM_ SG_ 2154921903 M2S_CMD1_CUS_Reserve3_31 "客户预留报文";
CM_ SG_ 2154921903 M2S_CMD1_CUS_Reserve4_31 "客户预留报文";
CM_ SG_ 2154921903 M2S_CMD1_CUS_Reserve5_31 "客户预留报文";
CM_ SG_ 2154921903 M2S_CMD1_CUS_Reserve6_31 "客户预留报文";
CM_ SG_ 2154921903 M2S_CMD1_CUS_Reserve7_31 "客户预留报文";
CM_ SG_ 2154921903 M2S_CMD1_CUS_Reserve8_31 "客户预留报文";
CM_ SG_ 2154987409 M2S_CMD2_CUS_Reserve1_01 "客户预留报文";
CM_ SG_ 2154987409 M2S_CMD2_CUS_Reserve2_01 "客户预留报文";
CM_ SG_ 2154987409 M2S_CMD2_CUS_Reserve3_01 "客户预留报文";
CM_ SG_ 2154987409 M2S_CMD2_CUS_Reserve4_01 "客户预留报文";
CM_ SG_ 2154987409 M2S_CMD2_CUS_Reserve5_01 "客户预留报文";
CM_ SG_ 2154987409 M2S_CMD2_CUS_Reserve6_01 "客户预留报文";
CM_ SG_ 2154987409 M2S_CMD2_CUS_Reserve7_01 "客户预留报文";
CM_ SG_ 2154987409 M2S_CMD2_CUS_Reserve8_01 "客户预留报文";
CM_ SG_ 2154987410 M2S_CMD2_CUS_Reserve1_02 "客户预留报文";
CM_ SG_ 2154987410 M2S_CMD2_CUS_Reserve2_02 "客户预留报文";
CM_ SG_ 2154987410 M2S_CMD2_CUS_Reserve3_02 "客户预留报文";
CM_ SG_ 2154987410 M2S_CMD2_CUS_Reserve4_02 "客户预留报文";
CM_ SG_ 2154987410 M2S_CMD2_CUS_Reserve5_02 "客户预留报文";
CM_ SG_ 2154987410 M2S_CMD2_CUS_Reserve6_02 "客户预留报文";
CM_ SG_ 2154987410 M2S_CMD2_CUS_Reserve7_02 "客户预留报文";
CM_ SG_ 2154987410 M2S_CMD2_CUS_Reserve8_02 "客户预留报文";
CM_ SG_ 2154987411 M2S_CMD2_CUS_Reserve1_03 "客户预留报文";
CM_ SG_ 2154987411 M2S_CMD2_CUS_Reserve2_03 "客户预留报文";
CM_ SG_ 2154987411 M2S_CMD2_CUS_Reserve3_03 "客户预留报文";
CM_ SG_ 2154987411 M2S_CMD2_CUS_Reserve4_03 "客户预留报文";
CM_ SG_ 2154987411 M2S_CMD2_CUS_Reserve5_03 "客户预留报文";
CM_ SG_ 2154987411 M2S_CMD2_CUS_Reserve6_03 "客户预留报文";
CM_ SG_ 2154987411 M2S_CMD2_CUS_Reserve7_03 "客户预留报文";
CM_ SG_ 2154987411 M2S_CMD2_CUS_Reserve8_03 "客户预留报文";
CM_ SG_ 2154987412 M2S_CMD2_CUS_Reserve1_04 "客户预留报文";
CM_ SG_ 2154987412 M2S_CMD2_CUS_Reserve2_04 "客户预留报文";
CM_ SG_ 2154987412 M2S_CMD2_CUS_Reserve3_04 "客户预留报文";
CM_ SG_ 2154987412 M2S_CMD2_CUS_Reserve4_04 "客户预留报文";
CM_ SG_ 2154987412 M2S_CMD2_CUS_Reserve5_04 "客户预留报文";
CM_ SG_ 2154987412 M2S_CMD2_CUS_Reserve6_04 "客户预留报文";
CM_ SG_ 2154987412 M2S_CMD2_CUS_Reserve7_04 "客户预留报文";
CM_ SG_ 2154987412 M2S_CMD2_CUS_Reserve8_04 "客户预留报文";
CM_ SG_ 2154987413 M2S_CMD2_CUS_Reserve1_05 "客户预留报文";
CM_ SG_ 2154987413 M2S_CMD2_CUS_Reserve2_05 "客户预留报文";
CM_ SG_ 2154987413 M2S_CMD2_CUS_Reserve3_05 "客户预留报文";
CM_ SG_ 2154987413 M2S_CMD2_CUS_Reserve4_05 "客户预留报文";
CM_ SG_ 2154987413 M2S_CMD2_CUS_Reserve5_05 "客户预留报文";
CM_ SG_ 2154987413 M2S_CMD2_CUS_Reserve6_05 "客户预留报文";
CM_ SG_ 2154987413 M2S_CMD2_CUS_Reserve7_05 "客户预留报文";
CM_ SG_ 2154987413 M2S_CMD2_CUS_Reserve8_05 "客户预留报文";
CM_ SG_ 2154987414 M2S_CMD2_CUS_Reserve1_06 "客户预留报文";
CM_ SG_ 2154987414 M2S_CMD2_CUS_Reserve2_06 "客户预留报文";
CM_ SG_ 2154987414 M2S_CMD2_CUS_Reserve3_06 "客户预留报文";
CM_ SG_ 2154987414 M2S_CMD2_CUS_Reserve4_06 "客户预留报文";
CM_ SG_ 2154987414 M2S_CMD2_CUS_Reserve5_06 "客户预留报文";
CM_ SG_ 2154987414 M2S_CMD2_CUS_Reserve6_06 "客户预留报文";
CM_ SG_ 2154987414 M2S_CMD2_CUS_Reserve7_06 "客户预留报文";
CM_ SG_ 2154987414 M2S_CMD2_CUS_Reserve8_06 "客户预留报文";
CM_ SG_ 2154987415 M2S_CMD2_CUS_Reserve1_07 "客户预留报文";
CM_ SG_ 2154987415 M2S_CMD2_CUS_Reserve2_07 "客户预留报文";
CM_ SG_ 2154987415 M2S_CMD2_CUS_Reserve3_07 "客户预留报文";
CM_ SG_ 2154987415 M2S_CMD2_CUS_Reserve4_07 "客户预留报文";
CM_ SG_ 2154987415 M2S_CMD2_CUS_Reserve5_07 "客户预留报文";
CM_ SG_ 2154987415 M2S_CMD2_CUS_Reserve6_07 "客户预留报文";
CM_ SG_ 2154987415 M2S_CMD2_CUS_Reserve7_07 "客户预留报文";
CM_ SG_ 2154987415 M2S_CMD2_CUS_Reserve8_07 "客户预留报文";
CM_ SG_ 2154987416 M2S_CMD2_CUS_Reserve1_08 "客户预留报文";
CM_ SG_ 2154987416 M2S_CMD2_CUS_Reserve2_08 "客户预留报文";
CM_ SG_ 2154987416 M2S_CMD2_CUS_Reserve3_08 "客户预留报文";
CM_ SG_ 2154987416 M2S_CMD2_CUS_Reserve4_08 "客户预留报文";
CM_ SG_ 2154987416 M2S_CMD2_CUS_Reserve5_08 "客户预留报文";
CM_ SG_ 2154987416 M2S_CMD2_CUS_Reserve6_08 "客户预留报文";
CM_ SG_ 2154987416 M2S_CMD2_CUS_Reserve7_08 "客户预留报文";
CM_ SG_ 2154987416 M2S_CMD2_CUS_Reserve8_08 "客户预留报文";
CM_ SG_ 2154987417 M2S_CMD2_CUS_Reserve1_09 "客户预留报文";
CM_ SG_ 2154987417 M2S_CMD2_CUS_Reserve2_09 "客户预留报文";
CM_ SG_ 2154987417 M2S_CMD2_CUS_Reserve3_09 "客户预留报文";
CM_ SG_ 2154987417 M2S_CMD2_CUS_Reserve4_09 "客户预留报文";
CM_ SG_ 2154987417 M2S_CMD2_CUS_Reserve5_09 "客户预留报文";
CM_ SG_ 2154987417 M2S_CMD2_CUS_Reserve6_09 "客户预留报文";
CM_ SG_ 2154987417 M2S_CMD2_CUS_Reserve7_09 "客户预留报文";
CM_ SG_ 2154987417 M2S_CMD2_CUS_Reserve8_09 "客户预留报文";
CM_ SG_ 2154987418 M2S_CMD2_CUS_Reserve1_10 "客户预留报文";
CM_ SG_ 2154987418 M2S_CMD2_CUS_Reserve2_10 "客户预留报文";
CM_ SG_ 2154987418 M2S_CMD2_CUS_Reserve3_10 "客户预留报文";
CM_ SG_ 2154987418 M2S_CMD2_CUS_Reserve4_10 "客户预留报文";
CM_ SG_ 2154987418 M2S_CMD2_CUS_Reserve5_10 "客户预留报文";
CM_ SG_ 2154987418 M2S_CMD2_CUS_Reserve6_10 "客户预留报文";
CM_ SG_ 2154987418 M2S_CMD2_CUS_Reserve7_10 "客户预留报文";
CM_ SG_ 2154987418 M2S_CMD2_CUS_Reserve8_10 "客户预留报文";
CM_ SG_ 2154987419 M2S_CMD2_CUS_Reserve1_11 "客户预留报文";
CM_ SG_ 2154987419 M2S_CMD2_CUS_Reserve2_11 "客户预留报文";
CM_ SG_ 2154987419 M2S_CMD2_CUS_Reserve3_11 "客户预留报文";
CM_ SG_ 2154987419 M2S_CMD2_CUS_Reserve4_11 "客户预留报文";
CM_ SG_ 2154987419 M2S_CMD2_CUS_Reserve5_11 "客户预留报文";
CM_ SG_ 2154987419 M2S_CMD2_CUS_Reserve6_11 "客户预留报文";
CM_ SG_ 2154987419 M2S_CMD2_CUS_Reserve7_11 "客户预留报文";
CM_ SG_ 2154987419 M2S_CMD2_CUS_Reserve8_11 "客户预留报文";
CM_ SG_ 2154987420 M2S_CMD2_CUS_Reserve1_12 "客户预留报文";
CM_ SG_ 2154987420 M2S_CMD2_CUS_Reserve2_12 "客户预留报文";
CM_ SG_ 2154987420 M2S_CMD2_CUS_Reserve3_12 "客户预留报文";
CM_ SG_ 2154987420 M2S_CMD2_CUS_Reserve4_12 "客户预留报文";
CM_ SG_ 2154987420 M2S_CMD2_CUS_Reserve5_12 "客户预留报文";
CM_ SG_ 2154987420 M2S_CMD2_CUS_Reserve6_12 "客户预留报文";
CM_ SG_ 2154987420 M2S_CMD2_CUS_Reserve7_12 "客户预留报文";
CM_ SG_ 2154987420 M2S_CMD2_CUS_Reserve8_12 "客户预留报文";
CM_ SG_ 2154987421 M2S_CMD2_CUS_Reserve1_13 "客户预留报文";
CM_ SG_ 2154987421 M2S_CMD2_CUS_Reserve2_13 "客户预留报文";
CM_ SG_ 2154987421 M2S_CMD2_CUS_Reserve3_13 "客户预留报文";
CM_ SG_ 2154987421 M2S_CMD2_CUS_Reserve4_13 "客户预留报文";
CM_ SG_ 2154987421 M2S_CMD2_CUS_Reserve5_13 "客户预留报文";
CM_ SG_ 2154987421 M2S_CMD2_CUS_Reserve6_13 "客户预留报文";
CM_ SG_ 2154987421 M2S_CMD2_CUS_Reserve7_13 "客户预留报文";
CM_ SG_ 2154987421 M2S_CMD2_CUS_Reserve8_13 "客户预留报文";
CM_ SG_ 2154987422 M2S_CMD2_CUS_Reserve1_14 "客户预留报文";
CM_ SG_ 2154987422 M2S_CMD2_CUS_Reserve2_14 "客户预留报文";
CM_ SG_ 2154987422 M2S_CMD2_CUS_Reserve3_14 "客户预留报文";
CM_ SG_ 2154987422 M2S_CMD2_CUS_Reserve4_14 "客户预留报文";
CM_ SG_ 2154987422 M2S_CMD2_CUS_Reserve5_14 "客户预留报文";
CM_ SG_ 2154987422 M2S_CMD2_CUS_Reserve6_14 "客户预留报文";
CM_ SG_ 2154987422 M2S_CMD2_CUS_Reserve7_14 "客户预留报文";
CM_ SG_ 2154987422 M2S_CMD2_CUS_Reserve8_14 "客户预留报文";
CM_ SG_ 2154987423 M2S_CMD2_CUS_Reserve1_15 "客户预留报文";
CM_ SG_ 2154987423 M2S_CMD2_CUS_Reserve2_15 "客户预留报文";
CM_ SG_ 2154987423 M2S_CMD2_CUS_Reserve3_15 "客户预留报文";
CM_ SG_ 2154987423 M2S_CMD2_CUS_Reserve4_15 "客户预留报文";
CM_ SG_ 2154987423 M2S_CMD2_CUS_Reserve5_15 "客户预留报文";
CM_ SG_ 2154987423 M2S_CMD2_CUS_Reserve6_15 "客户预留报文";
CM_ SG_ 2154987423 M2S_CMD2_CUS_Reserve7_15 "客户预留报文";
CM_ SG_ 2154987423 M2S_CMD2_CUS_Reserve8_15 "客户预留报文";
CM_ SG_ 2154987424 M2S_CMD2_CUS_Reserve1_16 "客户预留报文";
CM_ SG_ 2154987424 M2S_CMD2_CUS_Reserve2_16 "客户预留报文";
CM_ SG_ 2154987424 M2S_CMD2_CUS_Reserve3_16 "客户预留报文";
CM_ SG_ 2154987424 M2S_CMD2_CUS_Reserve4_16 "客户预留报文";
CM_ SG_ 2154987424 M2S_CMD2_CUS_Reserve5_16 "客户预留报文";
CM_ SG_ 2154987424 M2S_CMD2_CUS_Reserve6_16 "客户预留报文";
CM_ SG_ 2154987424 M2S_CMD2_CUS_Reserve7_16 "客户预留报文";
CM_ SG_ 2154987424 M2S_CMD2_CUS_Reserve8_16 "客户预留报文";
CM_ SG_ 2154987425 M2S_CMD2_CUS_Reserve1_17 "客户预留报文";
CM_ SG_ 2154987425 M2S_CMD2_CUS_Reserve2_17 "客户预留报文";
CM_ SG_ 2154987425 M2S_CMD2_CUS_Reserve3_17 "客户预留报文";
CM_ SG_ 2154987425 M2S_CMD2_CUS_Reserve4_17 "客户预留报文";
CM_ SG_ 2154987425 M2S_CMD2_CUS_Reserve5_17 "客户预留报文";
CM_ SG_ 2154987425 M2S_CMD2_CUS_Reserve6_17 "客户预留报文";
CM_ SG_ 2154987425 M2S_CMD2_CUS_Reserve7_17 "客户预留报文";
CM_ SG_ 2154987425 M2S_CMD2_CUS_Reserve8_17 "客户预留报文";
CM_ SG_ 2154987426 M2S_CMD2_CUS_Reserve1_18 "客户预留报文";
CM_ SG_ 2154987426 M2S_CMD2_CUS_Reserve2_18 "客户预留报文";
CM_ SG_ 2154987426 M2S_CMD2_CUS_Reserve3_18 "客户预留报文";
CM_ SG_ 2154987426 M2S_CMD2_CUS_Reserve4_18 "客户预留报文";
CM_ SG_ 2154987426 M2S_CMD2_CUS_Reserve5_18 "客户预留报文";
CM_ SG_ 2154987426 M2S_CMD2_CUS_Reserve6_18 "客户预留报文";
CM_ SG_ 2154987426 M2S_CMD2_CUS_Reserve7_18 "客户预留报文";
CM_ SG_ 2154987426 M2S_CMD2_CUS_Reserve8_18 "客户预留报文";
CM_ SG_ 2154987427 M2S_CMD2_CUS_Reserve1_19 "客户预留报文";
CM_ SG_ 2154987427 M2S_CMD2_CUS_Reserve2_19 "客户预留报文";
CM_ SG_ 2154987427 M2S_CMD2_CUS_Reserve3_19 "客户预留报文";
CM_ SG_ 2154987427 M2S_CMD2_CUS_Reserve4_19 "客户预留报文";
CM_ SG_ 2154987427 M2S_CMD2_CUS_Reserve5_19 "客户预留报文";
CM_ SG_ 2154987427 M2S_CMD2_CUS_Reserve6_19 "客户预留报文";
CM_ SG_ 2154987427 M2S_CMD2_CUS_Reserve7_19 "客户预留报文";
CM_ SG_ 2154987427 M2S_CMD2_CUS_Reserve8_19 "客户预留报文";
CM_ SG_ 2154987428 M2S_CMD2_CUS_Reserve1_20 "客户预留报文";
CM_ SG_ 2154987428 M2S_CMD2_CUS_Reserve2_20 "客户预留报文";
CM_ SG_ 2154987428 M2S_CMD2_CUS_Reserve3_20 "客户预留报文";
CM_ SG_ 2154987428 M2S_CMD2_CUS_Reserve4_20 "客户预留报文";
CM_ SG_ 2154987428 M2S_CMD2_CUS_Reserve5_20 "客户预留报文";
CM_ SG_ 2154987428 M2S_CMD2_CUS_Reserve6_20 "客户预留报文";
CM_ SG_ 2154987428 M2S_CMD2_CUS_Reserve7_20 "客户预留报文";
CM_ SG_ 2154987428 M2S_CMD2_CUS_Reserve8_20 "客户预留报文";
CM_ SG_ 2154987429 M2S_CMD2_CUS_Reserve1_21 "客户预留报文";
CM_ SG_ 2154987429 M2S_CMD2_CUS_Reserve2_21 "客户预留报文";
CM_ SG_ 2154987429 M2S_CMD2_CUS_Reserve3_21 "客户预留报文";
CM_ SG_ 2154987429 M2S_CMD2_CUS_Reserve4_21 "客户预留报文";
CM_ SG_ 2154987429 M2S_CMD2_CUS_Reserve5_21 "客户预留报文";
CM_ SG_ 2154987429 M2S_CMD2_CUS_Reserve6_21 "客户预留报文";
CM_ SG_ 2154987429 M2S_CMD2_CUS_Reserve7_21 "客户预留报文";
CM_ SG_ 2154987429 M2S_CMD2_CUS_Reserve8_21 "客户预留报文";
CM_ SG_ 2154987430 M2S_CMD2_CUS_Reserve1_22 "客户预留报文";
CM_ SG_ 2154987430 M2S_CMD2_CUS_Reserve2_22 "客户预留报文";
CM_ SG_ 2154987430 M2S_CMD2_CUS_Reserve3_22 "客户预留报文";
CM_ SG_ 2154987430 M2S_CMD2_CUS_Reserve4_22 "客户预留报文";
CM_ SG_ 2154987430 M2S_CMD2_CUS_Reserve5_22 "客户预留报文";
CM_ SG_ 2154987430 M2S_CMD2_CUS_Reserve6_22 "客户预留报文";
CM_ SG_ 2154987430 M2S_CMD2_CUS_Reserve7_22 "客户预留报文";
CM_ SG_ 2154987430 M2S_CMD2_CUS_Reserve8_22 "客户预留报文";
CM_ SG_ 2154987431 M2S_CMD2_CUS_Reserve1_23 "客户预留报文";
CM_ SG_ 2154987431 M2S_CMD2_CUS_Reserve2_23 "客户预留报文";
CM_ SG_ 2154987431 M2S_CMD2_CUS_Reserve3_23 "客户预留报文";
CM_ SG_ 2154987431 M2S_CMD2_CUS_Reserve4_23 "客户预留报文";
CM_ SG_ 2154987431 M2S_CMD2_CUS_Reserve5_23 "客户预留报文";
CM_ SG_ 2154987431 M2S_CMD2_CUS_Reserve6_23 "客户预留报文";
CM_ SG_ 2154987431 M2S_CMD2_CUS_Reserve7_23 "客户预留报文";
CM_ SG_ 2154987431 M2S_CMD2_CUS_Reserve8_23 "客户预留报文";
CM_ SG_ 2154987432 M2S_CMD2_CUS_Reserve1_24 "客户预留报文";
CM_ SG_ 2154987432 M2S_CMD2_CUS_Reserve2_24 "客户预留报文";
CM_ SG_ 2154987432 M2S_CMD2_CUS_Reserve3_24 "客户预留报文";
CM_ SG_ 2154987432 M2S_CMD2_CUS_Reserve4_24 "客户预留报文";
CM_ SG_ 2154987432 M2S_CMD2_CUS_Reserve5_24 "客户预留报文";
CM_ SG_ 2154987432 M2S_CMD2_CUS_Reserve6_24 "客户预留报文";
CM_ SG_ 2154987432 M2S_CMD2_CUS_Reserve7_24 "客户预留报文";
CM_ SG_ 2154987432 M2S_CMD2_CUS_Reserve8_24 "客户预留报文";
CM_ SG_ 2154987433 M2S_CMD2_CUS_Reserve1_25 "客户预留报文";
CM_ SG_ 2154987433 M2S_CMD2_CUS_Reserve2_25 "客户预留报文";
CM_ SG_ 2154987433 M2S_CMD2_CUS_Reserve3_25 "客户预留报文";
CM_ SG_ 2154987433 M2S_CMD2_CUS_Reserve4_25 "客户预留报文";
CM_ SG_ 2154987433 M2S_CMD2_CUS_Reserve5_25 "客户预留报文";
CM_ SG_ 2154987433 M2S_CMD2_CUS_Reserve6_25 "客户预留报文";
CM_ SG_ 2154987433 M2S_CMD2_CUS_Reserve7_25 "客户预留报文";
CM_ SG_ 2154987433 M2S_CMD2_CUS_Reserve8_25 "客户预留报文";
CM_ SG_ 2154987434 M2S_CMD2_CUS_Reserve1_26 "客户预留报文";
CM_ SG_ 2154987434 M2S_CMD2_CUS_Reserve2_26 "客户预留报文";
CM_ SG_ 2154987434 M2S_CMD2_CUS_Reserve3_26 "客户预留报文";
CM_ SG_ 2154987434 M2S_CMD2_CUS_Reserve4_26 "客户预留报文";
CM_ SG_ 2154987434 M2S_CMD2_CUS_Reserve5_26 "客户预留报文";
CM_ SG_ 2154987434 M2S_CMD2_CUS_Reserve6_26 "客户预留报文";
CM_ SG_ 2154987434 M2S_CMD2_CUS_Reserve7_26 "客户预留报文";
CM_ SG_ 2154987434 M2S_CMD2_CUS_Reserve8_26 "客户预留报文";
CM_ SG_ 2154987435 M2S_CMD2_CUS_Reserve1_27 "客户预留报文";
CM_ SG_ 2154987435 M2S_CMD2_CUS_Reserve2_27 "客户预留报文";
CM_ SG_ 2154987435 M2S_CMD2_CUS_Reserve3_27 "客户预留报文";
CM_ SG_ 2154987435 M2S_CMD2_CUS_Reserve4_27 "客户预留报文";
CM_ SG_ 2154987435 M2S_CMD2_CUS_Reserve5_27 "客户预留报文";
CM_ SG_ 2154987435 M2S_CMD2_CUS_Reserve6_27 "客户预留报文";
CM_ SG_ 2154987435 M2S_CMD2_CUS_Reserve7_27 "客户预留报文";
CM_ SG_ 2154987435 M2S_CMD2_CUS_Reserve8_27 "客户预留报文";
CM_ SG_ 2154987436 M2S_CMD2_CUS_Reserve1_28 "客户预留报文";
CM_ SG_ 2154987436 M2S_CMD2_CUS_Reserve2_28 "客户预留报文";
CM_ SG_ 2154987436 M2S_CMD2_CUS_Reserve3_28 "客户预留报文";
CM_ SG_ 2154987436 M2S_CMD2_CUS_Reserve4_28 "客户预留报文";
CM_ SG_ 2154987436 M2S_CMD2_CUS_Reserve5_28 "客户预留报文";
CM_ SG_ 2154987436 M2S_CMD2_CUS_Reserve6_28 "客户预留报文";
CM_ SG_ 2154987436 M2S_CMD2_CUS_Reserve7_28 "客户预留报文";
CM_ SG_ 2154987436 M2S_CMD2_CUS_Reserve8_28 "客户预留报文";
CM_ SG_ 2154987437 M2S_CMD2_CUS_Reserve1_29 "客户预留报文";
CM_ SG_ 2154987437 M2S_CMD2_CUS_Reserve2_29 "客户预留报文";
CM_ SG_ 2154987437 M2S_CMD2_CUS_Reserve3_29 "客户预留报文";
CM_ SG_ 2154987437 M2S_CMD2_CUS_Reserve4_29 "客户预留报文";
CM_ SG_ 2154987437 M2S_CMD2_CUS_Reserve5_29 "客户预留报文";
CM_ SG_ 2154987437 M2S_CMD2_CUS_Reserve6_29 "客户预留报文";
CM_ SG_ 2154987437 M2S_CMD2_CUS_Reserve7_29 "客户预留报文";
CM_ SG_ 2154987437 M2S_CMD2_CUS_Reserve8_29 "客户预留报文";
CM_ SG_ 2154987438 M2S_CMD2_CUS_Reserve1_30 "客户预留报文";
CM_ SG_ 2154987438 M2S_CMD2_CUS_Reserve2_30 "客户预留报文";
CM_ SG_ 2154987438 M2S_CMD2_CUS_Reserve3_30 "客户预留报文";
CM_ SG_ 2154987438 M2S_CMD2_CUS_Reserve4_30 "客户预留报文";
CM_ SG_ 2154987438 M2S_CMD2_CUS_Reserve5_30 "客户预留报文";
CM_ SG_ 2154987438 M2S_CMD2_CUS_Reserve6_30 "客户预留报文";
CM_ SG_ 2154987438 M2S_CMD2_CUS_Reserve7_30 "客户预留报文";
CM_ SG_ 2154987438 M2S_CMD2_CUS_Reserve8_30 "客户预留报文";
CM_ SG_ 2154987439 M2S_CMD2_CUS_Reserve1_31 "客户预留报文";
CM_ SG_ 2154987439 M2S_CMD2_CUS_Reserve2_31 "客户预留报文";
CM_ SG_ 2154987439 M2S_CMD2_CUS_Reserve3_31 "客户预留报文";
CM_ SG_ 2154987439 M2S_CMD2_CUS_Reserve4_31 "客户预留报文";
CM_ SG_ 2154987439 M2S_CMD2_CUS_Reserve5_31 "客户预留报文";
CM_ SG_ 2154987439 M2S_CMD2_CUS_Reserve6_31 "客户预留报文";
CM_ SG_ 2154987439 M2S_CMD2_CUS_Reserve7_31 "客户预留报文";
CM_ SG_ 2154987439 M2S_CMD2_CUS_Reserve8_31 "客户预留报文";
CM_ SG_ 2155052945 M2S_CMD3_CUS_Reserve1_01 "客户预留报文";
CM_ SG_ 2155052945 M2S_CMD3_CUS_Reserve2_01 "客户预留报文";
CM_ SG_ 2155052945 M2S_CMD3_CUS_Reserve3_01 "客户预留报文";
CM_ SG_ 2155052945 M2S_CMD3_CUS_Reserve4_01 "客户预留报文";
CM_ SG_ 2155052945 M2S_CMD3_CUS_Reserve5_01 "客户预留报文";
CM_ SG_ 2155052945 M2S_CMD3_CUS_Reserve6_01 "客户预留报文";
CM_ SG_ 2155052945 M2S_CMD3_CUS_Reserve7_01 "客户预留报文";
CM_ SG_ 2155052945 M2S_CMD3_CUS_Reserve8_01 "客户预留报文";
CM_ SG_ 2155052946 M2S_CMD3_CUS_Reserve1_02 "客户预留报文";
CM_ SG_ 2155052946 M2S_CMD3_CUS_Reserve2_02 "客户预留报文";
CM_ SG_ 2155052946 M2S_CMD3_CUS_Reserve3_02 "客户预留报文";
CM_ SG_ 2155052946 M2S_CMD3_CUS_Reserve4_02 "客户预留报文";
CM_ SG_ 2155052946 M2S_CMD3_CUS_Reserve5_02 "客户预留报文";
CM_ SG_ 2155052946 M2S_CMD3_CUS_Reserve6_02 "客户预留报文";
CM_ SG_ 2155052946 M2S_CMD3_CUS_Reserve7_02 "客户预留报文";
CM_ SG_ 2155052946 M2S_CMD3_CUS_Reserve8_02 "客户预留报文";
CM_ SG_ 2155052947 M2S_CMD3_CUS_Reserve1_03 "客户预留报文";
CM_ SG_ 2155052947 M2S_CMD3_CUS_Reserve2_03 "客户预留报文";
CM_ SG_ 2155052947 M2S_CMD3_CUS_Reserve3_03 "客户预留报文";
CM_ SG_ 2155052947 M2S_CMD3_CUS_Reserve4_03 "客户预留报文";
CM_ SG_ 2155052947 M2S_CMD3_CUS_Reserve5_03 "客户预留报文";
CM_ SG_ 2155052947 M2S_CMD3_CUS_Reserve6_03 "客户预留报文";
CM_ SG_ 2155052947 M2S_CMD3_CUS_Reserve7_03 "客户预留报文";
CM_ SG_ 2155052947 M2S_CMD3_CUS_Reserve8_03 "客户预留报文";
CM_ SG_ 2155052948 M2S_CMD3_CUS_Reserve1_04 "客户预留报文";
CM_ SG_ 2155052948 M2S_CMD3_CUS_Reserve2_04 "客户预留报文";
CM_ SG_ 2155052948 M2S_CMD3_CUS_Reserve3_04 "客户预留报文";
CM_ SG_ 2155052948 M2S_CMD3_CUS_Reserve4_04 "客户预留报文";
CM_ SG_ 2155052948 M2S_CMD3_CUS_Reserve5_04 "客户预留报文";
CM_ SG_ 2155052948 M2S_CMD3_CUS_Reserve6_04 "客户预留报文";
CM_ SG_ 2155052948 M2S_CMD3_CUS_Reserve7_04 "客户预留报文";
CM_ SG_ 2155052948 M2S_CMD3_CUS_Reserve8_04 "客户预留报文";
CM_ SG_ 2155052949 M2S_CMD3_CUS_Reserve1_05 "客户预留报文";
CM_ SG_ 2155052949 M2S_CMD3_CUS_Reserve2_05 "客户预留报文";
CM_ SG_ 2155052949 M2S_CMD3_CUS_Reserve3_05 "客户预留报文";
CM_ SG_ 2155052949 M2S_CMD3_CUS_Reserve4_05 "客户预留报文";
CM_ SG_ 2155052949 M2S_CMD3_CUS_Reserve5_05 "客户预留报文";
CM_ SG_ 2155052949 M2S_CMD3_CUS_Reserve6_05 "客户预留报文";
CM_ SG_ 2155052949 M2S_CMD3_CUS_Reserve7_05 "客户预留报文";
CM_ SG_ 2155052949 M2S_CMD3_CUS_Reserve8_05 "客户预留报文";
CM_ SG_ 2155052950 M2S_CMD3_CUS_Reserve1_06 "客户预留报文";
CM_ SG_ 2155052950 M2S_CMD3_CUS_Reserve2_06 "客户预留报文";
CM_ SG_ 2155052950 M2S_CMD3_CUS_Reserve3_06 "客户预留报文";
CM_ SG_ 2155052950 M2S_CMD3_CUS_Reserve4_06 "客户预留报文";
CM_ SG_ 2155052950 M2S_CMD3_CUS_Reserve5_06 "客户预留报文";
CM_ SG_ 2155052950 M2S_CMD3_CUS_Reserve6_06 "客户预留报文";
CM_ SG_ 2155052950 M2S_CMD3_CUS_Reserve7_06 "客户预留报文";
CM_ SG_ 2155052950 M2S_CMD3_CUS_Reserve8_06 "客户预留报文";
CM_ SG_ 2155052951 M2S_CMD3_CUS_Reserve1_07 "客户预留报文";
CM_ SG_ 2155052951 M2S_CMD3_CUS_Reserve2_07 "客户预留报文";
CM_ SG_ 2155052951 M2S_CMD3_CUS_Reserve3_07 "客户预留报文";
CM_ SG_ 2155052951 M2S_CMD3_CUS_Reserve4_07 "客户预留报文";
CM_ SG_ 2155052951 M2S_CMD3_CUS_Reserve5_07 "客户预留报文";
CM_ SG_ 2155052951 M2S_CMD3_CUS_Reserve6_07 "客户预留报文";
CM_ SG_ 2155052951 M2S_CMD3_CUS_Reserve7_07 "客户预留报文";
CM_ SG_ 2155052951 M2S_CMD3_CUS_Reserve8_07 "客户预留报文";
CM_ SG_ 2155052952 M2S_CMD3_CUS_Reserve1_08 "客户预留报文";
CM_ SG_ 2155052952 M2S_CMD3_CUS_Reserve2_08 "客户预留报文";
CM_ SG_ 2155052952 M2S_CMD3_CUS_Reserve3_08 "客户预留报文";
CM_ SG_ 2155052952 M2S_CMD3_CUS_Reserve4_08 "客户预留报文";
CM_ SG_ 2155052952 M2S_CMD3_CUS_Reserve5_08 "客户预留报文";
CM_ SG_ 2155052952 M2S_CMD3_CUS_Reserve6_08 "客户预留报文";
CM_ SG_ 2155052952 M2S_CMD3_CUS_Reserve7_08 "客户预留报文";
CM_ SG_ 2155052952 M2S_CMD3_CUS_Reserve8_08 "客户预留报文";
CM_ SG_ 2155052953 M2S_CMD3_CUS_Reserve1_09 "客户预留报文";
CM_ SG_ 2155052953 M2S_CMD3_CUS_Reserve2_09 "客户预留报文";
CM_ SG_ 2155052953 M2S_CMD3_CUS_Reserve3_09 "客户预留报文";
CM_ SG_ 2155052953 M2S_CMD3_CUS_Reserve4_09 "客户预留报文";
CM_ SG_ 2155052953 M2S_CMD3_CUS_Reserve5_09 "客户预留报文";
CM_ SG_ 2155052953 M2S_CMD3_CUS_Reserve6_09 "客户预留报文";
CM_ SG_ 2155052953 M2S_CMD3_CUS_Reserve7_09 "客户预留报文";
CM_ SG_ 2155052953 M2S_CMD3_CUS_Reserve8_09 "客户预留报文";
CM_ SG_ 2155052954 M2S_CMD3_CUS_Reserve1_10 "客户预留报文";
CM_ SG_ 2155052954 M2S_CMD3_CUS_Reserve2_10 "客户预留报文";
CM_ SG_ 2155052954 M2S_CMD3_CUS_Reserve3_10 "客户预留报文";
CM_ SG_ 2155052954 M2S_CMD3_CUS_Reserve4_10 "客户预留报文";
CM_ SG_ 2155052954 M2S_CMD3_CUS_Reserve5_10 "客户预留报文";
CM_ SG_ 2155052954 M2S_CMD3_CUS_Reserve6_10 "客户预留报文";
CM_ SG_ 2155052954 M2S_CMD3_CUS_Reserve7_10 "客户预留报文";
CM_ SG_ 2155052954 M2S_CMD3_CUS_Reserve8_10 "客户预留报文";
CM_ SG_ 2155052955 M2S_CMD3_CUS_Reserve1_11 "客户预留报文";
CM_ SG_ 2155052955 M2S_CMD3_CUS_Reserve2_11 "客户预留报文";
CM_ SG_ 2155052955 M2S_CMD3_CUS_Reserve3_11 "客户预留报文";
CM_ SG_ 2155052955 M2S_CMD3_CUS_Reserve4_11 "客户预留报文";
CM_ SG_ 2155052955 M2S_CMD3_CUS_Reserve5_11 "客户预留报文";
CM_ SG_ 2155052955 M2S_CMD3_CUS_Reserve6_11 "客户预留报文";
CM_ SG_ 2155052955 M2S_CMD3_CUS_Reserve7_11 "客户预留报文";
CM_ SG_ 2155052955 M2S_CMD3_CUS_Reserve8_11 "客户预留报文";
CM_ SG_ 2155052956 M2S_CMD3_CUS_Reserve1_12 "客户预留报文";
CM_ SG_ 2155052956 M2S_CMD3_CUS_Reserve2_12 "客户预留报文";
CM_ SG_ 2155052956 M2S_CMD3_CUS_Reserve3_12 "客户预留报文";
CM_ SG_ 2155052956 M2S_CMD3_CUS_Reserve4_12 "客户预留报文";
CM_ SG_ 2155052956 M2S_CMD3_CUS_Reserve5_12 "客户预留报文";
CM_ SG_ 2155052956 M2S_CMD3_CUS_Reserve6_12 "客户预留报文";
CM_ SG_ 2155052956 M2S_CMD3_CUS_Reserve7_12 "客户预留报文";
CM_ SG_ 2155052956 M2S_CMD3_CUS_Reserve8_12 "客户预留报文";
CM_ SG_ 2155052957 M2S_CMD3_CUS_Reserve1_13 "客户预留报文";
CM_ SG_ 2155052957 M2S_CMD3_CUS_Reserve2_13 "客户预留报文";
CM_ SG_ 2155052957 M2S_CMD3_CUS_Reserve3_13 "客户预留报文";
CM_ SG_ 2155052957 M2S_CMD3_CUS_Reserve4_13 "客户预留报文";
CM_ SG_ 2155052957 M2S_CMD3_CUS_Reserve5_13 "客户预留报文";
CM_ SG_ 2155052957 M2S_CMD3_CUS_Reserve6_13 "客户预留报文";
CM_ SG_ 2155052957 M2S_CMD3_CUS_Reserve7_13 "客户预留报文";
CM_ SG_ 2155052957 M2S_CMD3_CUS_Reserve8_13 "客户预留报文";
CM_ SG_ 2155052958 M2S_CMD3_CUS_Reserve1_14 "客户预留报文";
CM_ SG_ 2155052958 M2S_CMD3_CUS_Reserve2_14 "客户预留报文";
CM_ SG_ 2155052958 M2S_CMD3_CUS_Reserve3_14 "客户预留报文";
CM_ SG_ 2155052958 M2S_CMD3_CUS_Reserve4_14 "客户预留报文";
CM_ SG_ 2155052958 M2S_CMD3_CUS_Reserve5_14 "客户预留报文";
CM_ SG_ 2155052958 M2S_CMD3_CUS_Reserve6_14 "客户预留报文";
CM_ SG_ 2155052958 M2S_CMD3_CUS_Reserve7_14 "客户预留报文";
CM_ SG_ 2155052958 M2S_CMD3_CUS_Reserve8_14 "客户预留报文";
CM_ SG_ 2155052959 M2S_CMD3_CUS_Reserve1_15 "客户预留报文";
CM_ SG_ 2155052959 M2S_CMD3_CUS_Reserve2_15 "客户预留报文";
CM_ SG_ 2155052959 M2S_CMD3_CUS_Reserve3_15 "客户预留报文";
CM_ SG_ 2155052959 M2S_CMD3_CUS_Reserve4_15 "客户预留报文";
CM_ SG_ 2155052959 M2S_CMD3_CUS_Reserve5_15 "客户预留报文";
CM_ SG_ 2155052959 M2S_CMD3_CUS_Reserve6_15 "客户预留报文";
CM_ SG_ 2155052959 M2S_CMD3_CUS_Reserve7_15 "客户预留报文";
CM_ SG_ 2155052959 M2S_CMD3_CUS_Reserve8_15 "客户预留报文";
CM_ SG_ 2155052960 M2S_CMD3_CUS_Reserve1_16 "客户预留报文";
CM_ SG_ 2155052960 M2S_CMD3_CUS_Reserve2_16 "客户预留报文";
CM_ SG_ 2155052960 M2S_CMD3_CUS_Reserve3_16 "客户预留报文";
CM_ SG_ 2155052960 M2S_CMD3_CUS_Reserve4_16 "客户预留报文";
CM_ SG_ 2155052960 M2S_CMD3_CUS_Reserve5_16 "客户预留报文";
CM_ SG_ 2155052960 M2S_CMD3_CUS_Reserve6_16 "客户预留报文";
CM_ SG_ 2155052960 M2S_CMD3_CUS_Reserve7_16 "客户预留报文";
CM_ SG_ 2155052960 M2S_CMD3_CUS_Reserve8_16 "客户预留报文";
CM_ SG_ 2155052961 M2S_CMD3_CUS_Reserve1_17 "客户预留报文";
CM_ SG_ 2155052961 M2S_CMD3_CUS_Reserve2_17 "客户预留报文";
CM_ SG_ 2155052961 M2S_CMD3_CUS_Reserve3_17 "客户预留报文";
CM_ SG_ 2155052961 M2S_CMD3_CUS_Reserve4_17 "客户预留报文";
CM_ SG_ 2155052961 M2S_CMD3_CUS_Reserve5_17 "客户预留报文";
CM_ SG_ 2155052961 M2S_CMD3_CUS_Reserve6_17 "客户预留报文";
CM_ SG_ 2155052961 M2S_CMD3_CUS_Reserve7_17 "客户预留报文";
CM_ SG_ 2155052961 M2S_CMD3_CUS_Reserve8_17 "客户预留报文";
CM_ SG_ 2155052962 M2S_CMD3_CUS_Reserve1_18 "客户预留报文";
CM_ SG_ 2155052962 M2S_CMD3_CUS_Reserve2_18 "客户预留报文";
CM_ SG_ 2155052962 M2S_CMD3_CUS_Reserve3_18 "客户预留报文";
CM_ SG_ 2155052962 M2S_CMD3_CUS_Reserve4_18 "客户预留报文";
CM_ SG_ 2155052962 M2S_CMD3_CUS_Reserve5_18 "客户预留报文";
CM_ SG_ 2155052962 M2S_CMD3_CUS_Reserve6_18 "客户预留报文";
CM_ SG_ 2155052962 M2S_CMD3_CUS_Reserve7_18 "客户预留报文";
CM_ SG_ 2155052962 M2S_CMD3_CUS_Reserve8_18 "客户预留报文";
CM_ SG_ 2155052963 M2S_CMD3_CUS_Reserve1_19 "客户预留报文";
CM_ SG_ 2155052963 M2S_CMD3_CUS_Reserve2_19 "客户预留报文";
CM_ SG_ 2155052963 M2S_CMD3_CUS_Reserve3_19 "客户预留报文";
CM_ SG_ 2155052963 M2S_CMD3_CUS_Reserve4_19 "客户预留报文";
CM_ SG_ 2155052963 M2S_CMD3_CUS_Reserve5_19 "客户预留报文";
CM_ SG_ 2155052963 M2S_CMD3_CUS_Reserve6_19 "客户预留报文";
CM_ SG_ 2155052963 M2S_CMD3_CUS_Reserve7_19 "客户预留报文";
CM_ SG_ 2155052963 M2S_CMD3_CUS_Reserve8_19 "客户预留报文";
CM_ SG_ 2155052964 M2S_CMD3_CUS_Reserve1_20 "客户预留报文";
CM_ SG_ 2155052964 M2S_CMD3_CUS_Reserve2_20 "客户预留报文";
CM_ SG_ 2155052964 M2S_CMD3_CUS_Reserve3_20 "客户预留报文";
CM_ SG_ 2155052964 M2S_CMD3_CUS_Reserve4_20 "客户预留报文";
CM_ SG_ 2155052964 M2S_CMD3_CUS_Reserve5_20 "客户预留报文";
CM_ SG_ 2155052964 M2S_CMD3_CUS_Reserve6_20 "客户预留报文";
CM_ SG_ 2155052964 M2S_CMD3_CUS_Reserve7_20 "客户预留报文";
CM_ SG_ 2155052964 M2S_CMD3_CUS_Reserve8_20 "客户预留报文";
CM_ SG_ 2155052965 M2S_CMD3_CUS_Reserve1_21 "客户预留报文";
CM_ SG_ 2155052965 M2S_CMD3_CUS_Reserve2_21 "客户预留报文";
CM_ SG_ 2155052965 M2S_CMD3_CUS_Reserve3_21 "客户预留报文";
CM_ SG_ 2155052965 M2S_CMD3_CUS_Reserve4_21 "客户预留报文";
CM_ SG_ 2155052965 M2S_CMD3_CUS_Reserve5_21 "客户预留报文";
CM_ SG_ 2155052965 M2S_CMD3_CUS_Reserve6_21 "客户预留报文";
CM_ SG_ 2155052965 M2S_CMD3_CUS_Reserve7_21 "客户预留报文";
CM_ SG_ 2155052965 M2S_CMD3_CUS_Reserve8_21 "客户预留报文";
CM_ SG_ 2155052966 M2S_CMD3_CUS_Reserve1_22 "客户预留报文";
CM_ SG_ 2155052966 M2S_CMD3_CUS_Reserve2_22 "客户预留报文";
CM_ SG_ 2155052966 M2S_CMD3_CUS_Reserve3_22 "客户预留报文";
CM_ SG_ 2155052966 M2S_CMD3_CUS_Reserve4_22 "客户预留报文";
CM_ SG_ 2155052966 M2S_CMD3_CUS_Reserve5_22 "客户预留报文";
CM_ SG_ 2155052966 M2S_CMD3_CUS_Reserve6_22 "客户预留报文";
CM_ SG_ 2155052966 M2S_CMD3_CUS_Reserve7_22 "客户预留报文";
CM_ SG_ 2155052966 M2S_CMD3_CUS_Reserve8_22 "客户预留报文";
CM_ SG_ 2155052967 M2S_CMD3_CUS_Reserve1_23 "客户预留报文";
CM_ SG_ 2155052967 M2S_CMD3_CUS_Reserve2_23 "客户预留报文";
CM_ SG_ 2155052967 M2S_CMD3_CUS_Reserve3_23 "客户预留报文";
CM_ SG_ 2155052967 M2S_CMD3_CUS_Reserve4_23 "客户预留报文";
CM_ SG_ 2155052967 M2S_CMD3_CUS_Reserve5_23 "客户预留报文";
CM_ SG_ 2155052967 M2S_CMD3_CUS_Reserve6_23 "客户预留报文";
CM_ SG_ 2155052967 M2S_CMD3_CUS_Reserve7_23 "客户预留报文";
CM_ SG_ 2155052967 M2S_CMD3_CUS_Reserve8_23 "客户预留报文";
CM_ SG_ 2155052968 M2S_CMD3_CUS_Reserve1_24 "客户预留报文";
CM_ SG_ 2155052968 M2S_CMD3_CUS_Reserve2_24 "客户预留报文";
CM_ SG_ 2155052968 M2S_CMD3_CUS_Reserve3_24 "客户预留报文";
CM_ SG_ 2155052968 M2S_CMD3_CUS_Reserve4_24 "客户预留报文";
CM_ SG_ 2155052968 M2S_CMD3_CUS_Reserve5_24 "客户预留报文";
CM_ SG_ 2155052968 M2S_CMD3_CUS_Reserve6_24 "客户预留报文";
CM_ SG_ 2155052968 M2S_CMD3_CUS_Reserve7_24 "客户预留报文";
CM_ SG_ 2155052968 M2S_CMD3_CUS_Reserve8_24 "客户预留报文";
CM_ SG_ 2155052969 M2S_CMD3_CUS_Reserve1_25 "客户预留报文";
CM_ SG_ 2155052969 M2S_CMD3_CUS_Reserve2_25 "客户预留报文";
CM_ SG_ 2155052969 M2S_CMD3_CUS_Reserve3_25 "客户预留报文";
CM_ SG_ 2155052969 M2S_CMD3_CUS_Reserve4_25 "客户预留报文";
CM_ SG_ 2155052969 M2S_CMD3_CUS_Reserve5_25 "客户预留报文";
CM_ SG_ 2155052969 M2S_CMD3_CUS_Reserve6_25 "客户预留报文";
CM_ SG_ 2155052969 M2S_CMD3_CUS_Reserve7_25 "客户预留报文";
CM_ SG_ 2155052969 M2S_CMD3_CUS_Reserve8_25 "客户预留报文";
CM_ SG_ 2155052970 M2S_CMD3_CUS_Reserve1_26 "客户预留报文";
CM_ SG_ 2155052970 M2S_CMD3_CUS_Reserve2_26 "客户预留报文";
CM_ SG_ 2155052970 M2S_CMD3_CUS_Reserve3_26 "客户预留报文";
CM_ SG_ 2155052970 M2S_CMD3_CUS_Reserve4_26 "客户预留报文";
CM_ SG_ 2155052970 M2S_CMD3_CUS_Reserve5_26 "客户预留报文";
CM_ SG_ 2155052970 M2S_CMD3_CUS_Reserve6_26 "客户预留报文";
CM_ SG_ 2155052970 M2S_CMD3_CUS_Reserve7_26 "客户预留报文";
CM_ SG_ 2155052970 M2S_CMD3_CUS_Reserve8_26 "客户预留报文";
CM_ SG_ 2155052971 M2S_CMD3_CUS_Reserve1_27 "客户预留报文";
CM_ SG_ 2155052971 M2S_CMD3_CUS_Reserve2_27 "客户预留报文";
CM_ SG_ 2155052971 M2S_CMD3_CUS_Reserve3_27 "客户预留报文";
CM_ SG_ 2155052971 M2S_CMD3_CUS_Reserve4_27 "客户预留报文";
CM_ SG_ 2155052971 M2S_CMD3_CUS_Reserve5_27 "客户预留报文";
CM_ SG_ 2155052971 M2S_CMD3_CUS_Reserve6_27 "客户预留报文";
CM_ SG_ 2155052971 M2S_CMD3_CUS_Reserve7_27 "客户预留报文";
CM_ SG_ 2155052971 M2S_CMD3_CUS_Reserve8_27 "客户预留报文";
CM_ SG_ 2155052972 M2S_CMD3_CUS_Reserve1_28 "客户预留报文";
CM_ SG_ 2155052972 M2S_CMD3_CUS_Reserve2_28 "客户预留报文";
CM_ SG_ 2155052972 M2S_CMD3_CUS_Reserve3_28 "客户预留报文";
CM_ SG_ 2155052972 M2S_CMD3_CUS_Reserve4_28 "客户预留报文";
CM_ SG_ 2155052972 M2S_CMD3_CUS_Reserve5_28 "客户预留报文";
CM_ SG_ 2155052972 M2S_CMD3_CUS_Reserve6_28 "客户预留报文";
CM_ SG_ 2155052972 M2S_CMD3_CUS_Reserve7_28 "客户预留报文";
CM_ SG_ 2155052972 M2S_CMD3_CUS_Reserve8_28 "客户预留报文";
CM_ SG_ 2155052973 M2S_CMD3_CUS_Reserve1_29 "客户预留报文";
CM_ SG_ 2155052973 M2S_CMD3_CUS_Reserve2_29 "客户预留报文";
CM_ SG_ 2155052973 M2S_CMD3_CUS_Reserve3_29 "客户预留报文";
CM_ SG_ 2155052973 M2S_CMD3_CUS_Reserve4_29 "客户预留报文";
CM_ SG_ 2155052973 M2S_CMD3_CUS_Reserve5_29 "客户预留报文";
CM_ SG_ 2155052973 M2S_CMD3_CUS_Reserve6_29 "客户预留报文";
CM_ SG_ 2155052973 M2S_CMD3_CUS_Reserve7_29 "客户预留报文";
CM_ SG_ 2155052973 M2S_CMD3_CUS_Reserve8_29 "客户预留报文";
CM_ SG_ 2155052974 M2S_CMD3_CUS_Reserve1_30 "客户预留报文";
CM_ SG_ 2155052974 M2S_CMD3_CUS_Reserve2_30 "客户预留报文";
CM_ SG_ 2155052974 M2S_CMD3_CUS_Reserve3_30 "客户预留报文";
CM_ SG_ 2155052974 M2S_CMD3_CUS_Reserve4_30 "客户预留报文";
CM_ SG_ 2155052974 M2S_CMD3_CUS_Reserve5_30 "客户预留报文";
CM_ SG_ 2155052974 M2S_CMD3_CUS_Reserve6_30 "客户预留报文";
CM_ SG_ 2155052974 M2S_CMD3_CUS_Reserve7_30 "客户预留报文";
CM_ SG_ 2155052974 M2S_CMD3_CUS_Reserve8_30 "客户预留报文";
CM_ SG_ 2155052975 M2S_CMD3_CUS_Reserve1_31 "客户预留报文";
CM_ SG_ 2155052975 M2S_CMD3_CUS_Reserve2_31 "客户预留报文";
CM_ SG_ 2155052975 M2S_CMD3_CUS_Reserve3_31 "客户预留报文";
CM_ SG_ 2155052975 M2S_CMD3_CUS_Reserve4_31 "客户预留报文";
CM_ SG_ 2155052975 M2S_CMD3_CUS_Reserve5_31 "客户预留报文";
CM_ SG_ 2155052975 M2S_CMD3_CUS_Reserve6_31 "客户预留报文";
CM_ SG_ 2155052975 M2S_CMD3_CUS_Reserve7_31 "客户预留报文";
CM_ SG_ 2155052975 M2S_CMD3_CUS_Reserve8_31 "客户预留报文";
CM_ SG_ 2148827025 U2T_BMS_ControlMode_1 "BMS请求1号TMS设定模式";
CM_ SG_ 2148827025 T2U_TMS_RunState_1 "1号TMS运行状态";
CM_ SG_ 2148827025 T2U_TMS_FaultCode_1 "1号TMS故障码";
CM_ SG_ 2148827025 T2U_TMS_FaultLevel_1 "1号TMS故障码等级";
CM_ SG_ 2148827025 U2T_BMS_TmptSetPoint_1 "1号TMS BMS设定温度";
CM_ SG_ 2148827025 T2U_TMS_OutWaterTemp_1 "1号TMS出水温度";
CM_ SG_ 2148827025 T2U_TMS_BackWaterTemp_1 "1号TMS回水温度";
CM_ SG_ 2148827025 T2U_TMS_EnvTemp_1 "1号TMS环境温度";
CM_ SG_ 2148827025 M2P_TMSCoolingProtectMode_1_01 "1号TMS_制冷模式保护";
CM_ SG_ 2148827026 U2T_BMS_ControlMode_1 "BMS请求1号TMS设定模式";
CM_ SG_ 2148827026 T2U_TMS_RunState_1 "1号TMS运行状态";
CM_ SG_ 2148827026 T2U_TMS_FaultCode_1 "1号TMS故障码";
CM_ SG_ 2148827026 T2U_TMS_FaultLevel_1 "1号TMS故障码等级";
CM_ SG_ 2148827026 U2T_BMS_TmptSetPoint_1 "1号TMS BMS设定温度";
CM_ SG_ 2148827026 T2U_TMS_OutWaterTemp_1 "1号TMS出水温度";
CM_ SG_ 2148827026 T2U_TMS_BackWaterTemp_1 "1号TMS回水温度";
CM_ SG_ 2148827026 T2U_TMS_EnvTemp_1 "1号TMS环境温度";
CM_ SG_ 2148827026 M2P_TMSCoolingProtectMode_1_02 "1号TMS_制冷模式保护";
CM_ SG_ 2148827027 U2T_BMS_ControlMode_1 "BMS请求1号TMS设定模式";
CM_ SG_ 2148827027 T2U_TMS_RunState_1 "1号TMS运行状态";
CM_ SG_ 2148827027 T2U_TMS_FaultCode_1 "1号TMS故障码";
CM_ SG_ 2148827027 T2U_TMS_FaultLevel_1 "1号TMS故障码等级";
CM_ SG_ 2148827027 U2T_BMS_TmptSetPoint_1 "1号TMS BMS设定温度";
CM_ SG_ 2148827027 T2U_TMS_OutWaterTemp_1 "1号TMS出水温度";
CM_ SG_ 2148827027 T2U_TMS_BackWaterTemp_1 "1号TMS回水温度";
CM_ SG_ 2148827027 T2U_TMS_EnvTemp_1 "1号TMS环境温度";
CM_ SG_ 2148827027 M2P_TMSCoolingProtectMode_1_03 "1号TMS_制冷模式保护";
CM_ SG_ 2148827028 U2T_BMS_ControlMode_1 "BMS请求1号TMS设定模式";
CM_ SG_ 2148827028 T2U_TMS_RunState_1 "1号TMS运行状态";
CM_ SG_ 2148827028 T2U_TMS_FaultCode_1 "1号TMS故障码";
CM_ SG_ 2148827028 T2U_TMS_FaultLevel_1 "1号TMS故障码等级";
CM_ SG_ 2148827028 U2T_BMS_TmptSetPoint_1 "1号TMS BMS设定温度";
CM_ SG_ 2148827028 T2U_TMS_OutWaterTemp_1 "1号TMS出水温度";
CM_ SG_ 2148827028 T2U_TMS_BackWaterTemp_1 "1号TMS回水温度";
CM_ SG_ 2148827028 T2U_TMS_EnvTemp_1 "1号TMS环境温度";
CM_ SG_ 2148827028 M2P_TMSCoolingProtectMode_1_04 "1号TMS_制冷模式保护";
CM_ SG_ 2148827029 U2T_BMS_ControlMode_1 "BMS请求1号TMS设定模式";
CM_ SG_ 2148827029 T2U_TMS_RunState_1 "1号TMS运行状态";
CM_ SG_ 2148827029 T2U_TMS_FaultCode_1 "1号TMS故障码";
CM_ SG_ 2148827029 T2U_TMS_FaultLevel_1 "1号TMS故障码等级";
CM_ SG_ 2148827029 U2T_BMS_TmptSetPoint_1 "1号TMS BMS设定温度";
CM_ SG_ 2148827029 T2U_TMS_OutWaterTemp_1 "1号TMS出水温度";
CM_ SG_ 2148827029 T2U_TMS_BackWaterTemp_1 "1号TMS回水温度";
CM_ SG_ 2148827029 T2U_TMS_EnvTemp_1 "1号TMS环境温度";
CM_ SG_ 2148827029 M2P_TMSCoolingProtectMode_1_05 "1号TMS_制冷模式保护";
CM_ SG_ 2148827030 U2T_BMS_ControlMode_1 "BMS请求1号TMS设定模式";
CM_ SG_ 2148827030 T2U_TMS_RunState_1 "1号TMS运行状态";
CM_ SG_ 2148827030 T2U_TMS_FaultCode_1 "1号TMS故障码";
CM_ SG_ 2148827030 T2U_TMS_FaultLevel_1 "1号TMS故障码等级";
CM_ SG_ 2148827030 U2T_BMS_TmptSetPoint_1 "1号TMS BMS设定温度";
CM_ SG_ 2148827030 T2U_TMS_OutWaterTemp_1 "1号TMS出水温度";
CM_ SG_ 2148827030 T2U_TMS_BackWaterTemp_1 "1号TMS回水温度";
CM_ SG_ 2148827030 T2U_TMS_EnvTemp_1 "1号TMS环境温度";
CM_ SG_ 2148827030 M2P_TMSCoolingProtectMode_1_06 "1号TMS_制冷模式保护";
CM_ SG_ 2148827031 U2T_BMS_ControlMode_1 "BMS请求1号TMS设定模式";
CM_ SG_ 2148827031 T2U_TMS_RunState_1 "1号TMS运行状态";
CM_ SG_ 2148827031 T2U_TMS_FaultCode_1 "1号TMS故障码";
CM_ SG_ 2148827031 T2U_TMS_FaultLevel_1 "1号TMS故障码等级";
CM_ SG_ 2148827031 U2T_BMS_TmptSetPoint_1 "1号TMS BMS设定温度";
CM_ SG_ 2148827031 T2U_TMS_OutWaterTemp_1 "1号TMS出水温度";
CM_ SG_ 2148827031 T2U_TMS_BackWaterTemp_1 "1号TMS回水温度";
CM_ SG_ 2148827031 T2U_TMS_EnvTemp_1 "1号TMS环境温度";
CM_ SG_ 2148827031 M2P_TMSCoolingProtectMode_1_07 "1号TMS_制冷模式保护";
CM_ SG_ 2148827032 U2T_BMS_ControlMode_1 "BMS请求1号TMS设定模式";
CM_ SG_ 2148827032 T2U_TMS_RunState_1 "1号TMS运行状态";
CM_ SG_ 2148827032 T2U_TMS_FaultCode_1 "1号TMS故障码";
CM_ SG_ 2148827032 T2U_TMS_FaultLevel_1 "1号TMS故障码等级";
CM_ SG_ 2148827032 U2T_BMS_TmptSetPoint_1 "1号TMS BMS设定温度";
CM_ SG_ 2148827032 T2U_TMS_OutWaterTemp_1 "1号TMS出水温度";
CM_ SG_ 2148827032 T2U_TMS_BackWaterTemp_1 "1号TMS回水温度";
CM_ SG_ 2148827032 T2U_TMS_EnvTemp_1 "1号TMS环境温度";
CM_ SG_ 2148827032 M2P_TMSCoolingProtectMode_1_08 "1号TMS_制冷模式保护";
CM_ SG_ 2148827033 U2T_BMS_ControlMode_1 "BMS请求1号TMS设定模式";
CM_ SG_ 2148827033 T2U_TMS_RunState_1 "1号TMS运行状态";
CM_ SG_ 2148827033 T2U_TMS_FaultCode_1 "1号TMS故障码";
CM_ SG_ 2148827033 T2U_TMS_FaultLevel_1 "1号TMS故障码等级";
CM_ SG_ 2148827033 U2T_BMS_TmptSetPoint_1 "1号TMS BMS设定温度";
CM_ SG_ 2148827033 T2U_TMS_OutWaterTemp_1 "1号TMS出水温度";
CM_ SG_ 2148827033 T2U_TMS_BackWaterTemp_1 "1号TMS回水温度";
CM_ SG_ 2148827033 T2U_TMS_EnvTemp_1 "1号TMS环境温度";
CM_ SG_ 2148827033 M2P_TMSCoolingProtectMode_1_09 "1号TMS_制冷模式保护";
CM_ SG_ 2148827034 U2T_BMS_ControlMode_1 "BMS请求1号TMS设定模式";
CM_ SG_ 2148827034 T2U_TMS_RunState_1 "1号TMS运行状态";
CM_ SG_ 2148827034 T2U_TMS_FaultCode_1 "1号TMS故障码";
CM_ SG_ 2148827034 T2U_TMS_FaultLevel_1 "1号TMS故障码等级";
CM_ SG_ 2148827034 U2T_BMS_TmptSetPoint_1 "1号TMS BMS设定温度";
CM_ SG_ 2148827034 T2U_TMS_OutWaterTemp_1 "1号TMS出水温度";
CM_ SG_ 2148827034 T2U_TMS_BackWaterTemp_1 "1号TMS回水温度";
CM_ SG_ 2148827034 T2U_TMS_EnvTemp_1 "1号TMS环境温度";
CM_ SG_ 2148827034 M2P_TMSCoolingProtectMode_1_10 "1号TMS_制冷模式保护";
CM_ SG_ 2148827035 U2T_BMS_ControlMode_1 "BMS请求1号TMS设定模式";
CM_ SG_ 2148827035 T2U_TMS_RunState_1 "1号TMS运行状态";
CM_ SG_ 2148827035 T2U_TMS_FaultCode_1 "1号TMS故障码";
CM_ SG_ 2148827035 T2U_TMS_FaultLevel_1 "1号TMS故障码等级";
CM_ SG_ 2148827035 U2T_BMS_TmptSetPoint_1 "1号TMS BMS设定温度";
CM_ SG_ 2148827035 T2U_TMS_OutWaterTemp_1 "1号TMS出水温度";
CM_ SG_ 2148827035 T2U_TMS_BackWaterTemp_1 "1号TMS回水温度";
CM_ SG_ 2148827035 T2U_TMS_EnvTemp_1 "1号TMS环境温度";
CM_ SG_ 2148827035 M2P_TMSCoolingProtectMode_1_11 "1号TMS_制冷模式保护";
CM_ SG_ 2148827036 U2T_BMS_ControlMode_1 "BMS请求1号TMS设定模式";
CM_ SG_ 2148827036 T2U_TMS_RunState_1 "1号TMS运行状态";
CM_ SG_ 2148827036 T2U_TMS_FaultCode_1 "1号TMS故障码";
CM_ SG_ 2148827036 T2U_TMS_FaultLevel_1 "1号TMS故障码等级";
CM_ SG_ 2148827036 U2T_BMS_TmptSetPoint_1 "1号TMS BMS设定温度";
CM_ SG_ 2148827036 T2U_TMS_OutWaterTemp_1 "1号TMS出水温度";
CM_ SG_ 2148827036 T2U_TMS_BackWaterTemp_1 "1号TMS回水温度";
CM_ SG_ 2148827036 T2U_TMS_EnvTemp_1 "1号TMS环境温度";
CM_ SG_ 2148827036 M2P_TMSCoolingProtectMode_1_12 "1号TMS_制冷模式保护";
CM_ SG_ 2148827037 U2T_BMS_ControlMode_1 "BMS请求1号TMS设定模式";
CM_ SG_ 2148827037 T2U_TMS_RunState_1 "1号TMS运行状态";
CM_ SG_ 2148827037 T2U_TMS_FaultCode_1 "1号TMS故障码";
CM_ SG_ 2148827037 T2U_TMS_FaultLevel_1 "1号TMS故障码等级";
CM_ SG_ 2148827037 U2T_BMS_TmptSetPoint_1 "1号TMS BMS设定温度";
CM_ SG_ 2148827037 T2U_TMS_OutWaterTemp_1 "1号TMS出水温度";
CM_ SG_ 2148827037 T2U_TMS_BackWaterTemp_1 "1号TMS回水温度";
CM_ SG_ 2148827037 T2U_TMS_EnvTemp_1 "1号TMS环境温度";
CM_ SG_ 2148827037 M2P_TMSCoolingProtectMode_1_13 "1号TMS_制冷模式保护";
CM_ SG_ 2148827038 U2T_BMS_ControlMode_1 "BMS请求1号TMS设定模式";
CM_ SG_ 2148827038 T2U_TMS_RunState_1 "1号TMS运行状态";
CM_ SG_ 2148827038 T2U_TMS_FaultCode_1 "1号TMS故障码";
CM_ SG_ 2148827038 T2U_TMS_FaultLevel_1 "1号TMS故障码等级";
CM_ SG_ 2148827038 U2T_BMS_TmptSetPoint_1 "1号TMS BMS设定温度";
CM_ SG_ 2148827038 T2U_TMS_OutWaterTemp_1 "1号TMS出水温度";
CM_ SG_ 2148827038 T2U_TMS_BackWaterTemp_1 "1号TMS回水温度";
CM_ SG_ 2148827038 T2U_TMS_EnvTemp_1 "1号TMS环境温度";
CM_ SG_ 2148827038 M2P_TMSCoolingProtectMode_1_14 "1号TMS_制冷模式保护";
CM_ SG_ 2148827039 U2T_BMS_ControlMode_1 "BMS请求1号TMS设定模式";
CM_ SG_ 2148827039 T2U_TMS_RunState_1 "1号TMS运行状态";
CM_ SG_ 2148827039 T2U_TMS_FaultCode_1 "1号TMS故障码";
CM_ SG_ 2148827039 T2U_TMS_FaultLevel_1 "1号TMS故障码等级";
CM_ SG_ 2148827039 U2T_BMS_TmptSetPoint_1 "1号TMS BMS设定温度";
CM_ SG_ 2148827039 T2U_TMS_OutWaterTemp_1 "1号TMS出水温度";
CM_ SG_ 2148827039 T2U_TMS_BackWaterTemp_1 "1号TMS回水温度";
CM_ SG_ 2148827039 T2U_TMS_EnvTemp_1 "1号TMS环境温度";
CM_ SG_ 2148827039 M2P_TMSCoolingProtectMode_1_15 "1号TMS_制冷模式保护";
CM_ SG_ 2148827040 U2T_BMS_ControlMode_1 "BMS请求1号TMS设定模式";
CM_ SG_ 2148827040 T2U_TMS_RunState_1 "1号TMS运行状态";
CM_ SG_ 2148827040 T2U_TMS_FaultCode_1 "1号TMS故障码";
CM_ SG_ 2148827040 T2U_TMS_FaultLevel_1 "1号TMS故障码等级";
CM_ SG_ 2148827040 U2T_BMS_TmptSetPoint_1 "1号TMS BMS设定温度";
CM_ SG_ 2148827040 T2U_TMS_OutWaterTemp_1 "1号TMS出水温度";
CM_ SG_ 2148827040 T2U_TMS_BackWaterTemp_1 "1号TMS回水温度";
CM_ SG_ 2148827040 T2U_TMS_EnvTemp_1 "1号TMS环境温度";
CM_ SG_ 2148827040 M2P_TMSCoolingProtectMode_1_16 "1号TMS_制冷模式保护";
CM_ SG_ 2148827041 U2T_BMS_ControlMode_1 "BMS请求1号TMS设定模式";
CM_ SG_ 2148827041 T2U_TMS_RunState_1 "1号TMS运行状态";
CM_ SG_ 2148827041 T2U_TMS_FaultCode_1 "1号TMS故障码";
CM_ SG_ 2148827041 T2U_TMS_FaultLevel_1 "1号TMS故障码等级";
CM_ SG_ 2148827041 U2T_BMS_TmptSetPoint_1 "1号TMS BMS设定温度";
CM_ SG_ 2148827041 T2U_TMS_OutWaterTemp_1 "1号TMS出水温度";
CM_ SG_ 2148827041 T2U_TMS_BackWaterTemp_1 "1号TMS回水温度";
CM_ SG_ 2148827041 T2U_TMS_EnvTemp_1 "1号TMS环境温度";
CM_ SG_ 2148827041 M2P_TMSCoolingProtectMode_1_17 "1号TMS_制冷模式保护";
CM_ SG_ 2148827042 U2T_BMS_ControlMode_1 "BMS请求1号TMS设定模式";
CM_ SG_ 2148827042 T2U_TMS_RunState_1 "1号TMS运行状态";
CM_ SG_ 2148827042 T2U_TMS_FaultCode_1 "1号TMS故障码";
CM_ SG_ 2148827042 T2U_TMS_FaultLevel_1 "1号TMS故障码等级";
CM_ SG_ 2148827042 U2T_BMS_TmptSetPoint_1 "1号TMS BMS设定温度";
CM_ SG_ 2148827042 T2U_TMS_OutWaterTemp_1 "1号TMS出水温度";
CM_ SG_ 2148827042 T2U_TMS_BackWaterTemp_1 "1号TMS回水温度";
CM_ SG_ 2148827042 T2U_TMS_EnvTemp_1 "1号TMS环境温度";
CM_ SG_ 2148827042 M2P_TMSCoolingProtectMode_1_18 "1号TMS_制冷模式保护";
CM_ SG_ 2148827043 U2T_BMS_ControlMode_1 "BMS请求1号TMS设定模式";
CM_ SG_ 2148827043 T2U_TMS_RunState_1 "1号TMS运行状态";
CM_ SG_ 2148827043 T2U_TMS_FaultCode_1 "1号TMS故障码";
CM_ SG_ 2148827043 T2U_TMS_FaultLevel_1 "1号TMS故障码等级";
CM_ SG_ 2148827043 U2T_BMS_TmptSetPoint_1 "1号TMS BMS设定温度";
CM_ SG_ 2148827043 T2U_TMS_OutWaterTemp_1 "1号TMS出水温度";
CM_ SG_ 2148827043 T2U_TMS_BackWaterTemp_1 "1号TMS回水温度";
CM_ SG_ 2148827043 T2U_TMS_EnvTemp_1 "1号TMS环境温度";
CM_ SG_ 2148827043 M2P_TMSCoolingProtectMode_1_19 "1号TMS_制冷模式保护";
CM_ SG_ 2148827044 U2T_BMS_ControlMode_1 "BMS请求1号TMS设定模式";
CM_ SG_ 2148827044 T2U_TMS_RunState_1 "1号TMS运行状态";
CM_ SG_ 2148827044 T2U_TMS_FaultCode_1 "1号TMS故障码";
CM_ SG_ 2148827044 T2U_TMS_FaultLevel_1 "1号TMS故障码等级";
CM_ SG_ 2148827044 U2T_BMS_TmptSetPoint_1 "1号TMS BMS设定温度";
CM_ SG_ 2148827044 T2U_TMS_OutWaterTemp_1 "1号TMS出水温度";
CM_ SG_ 2148827044 T2U_TMS_BackWaterTemp_1 "1号TMS回水温度";
CM_ SG_ 2148827044 T2U_TMS_EnvTemp_1 "1号TMS环境温度";
CM_ SG_ 2148827044 M2P_TMSCoolingProtectMode_1_20 "1号TMS_制冷模式保护";
CM_ SG_ 2148827045 U2T_BMS_ControlMode_1 "BMS请求1号TMS设定模式";
CM_ SG_ 2148827045 T2U_TMS_RunState_1 "1号TMS运行状态";
CM_ SG_ 2148827045 T2U_TMS_FaultCode_1 "1号TMS故障码";
CM_ SG_ 2148827045 T2U_TMS_FaultLevel_1 "1号TMS故障码等级";
CM_ SG_ 2148827045 U2T_BMS_TmptSetPoint_1 "1号TMS BMS设定温度";
CM_ SG_ 2148827045 T2U_TMS_OutWaterTemp_1 "1号TMS出水温度";
CM_ SG_ 2148827045 T2U_TMS_BackWaterTemp_1 "1号TMS回水温度";
CM_ SG_ 2148827045 T2U_TMS_EnvTemp_1 "1号TMS环境温度";
CM_ SG_ 2148827045 M2P_TMSCoolingProtectMode_1_21 "1号TMS_制冷模式保护";
CM_ SG_ 2148827046 U2T_BMS_ControlMode_1 "BMS请求1号TMS设定模式";
CM_ SG_ 2148827046 T2U_TMS_RunState_1 "1号TMS运行状态";
CM_ SG_ 2148827046 T2U_TMS_FaultCode_1 "1号TMS故障码";
CM_ SG_ 2148827046 T2U_TMS_FaultLevel_1 "1号TMS故障码等级";
CM_ SG_ 2148827046 U2T_BMS_TmptSetPoint_1 "1号TMS BMS设定温度";
CM_ SG_ 2148827046 T2U_TMS_OutWaterTemp_1 "1号TMS出水温度";
CM_ SG_ 2148827046 T2U_TMS_BackWaterTemp_1 "1号TMS回水温度";
CM_ SG_ 2148827046 T2U_TMS_EnvTemp_1 "1号TMS环境温度";
CM_ SG_ 2148827046 M2P_TMSCoolingProtectMode_1_22 "1号TMS_制冷模式保护";
CM_ SG_ 2148827047 U2T_BMS_ControlMode_1 "BMS请求1号TMS设定模式";
CM_ SG_ 2148827047 T2U_TMS_RunState_1 "1号TMS运行状态";
CM_ SG_ 2148827047 T2U_TMS_FaultCode_1 "1号TMS故障码";
CM_ SG_ 2148827047 T2U_TMS_FaultLevel_1 "1号TMS故障码等级";
CM_ SG_ 2148827047 U2T_BMS_TmptSetPoint_1 "1号TMS BMS设定温度";
CM_ SG_ 2148827047 T2U_TMS_OutWaterTemp_1 "1号TMS出水温度";
CM_ SG_ 2148827047 T2U_TMS_BackWaterTemp_1 "1号TMS回水温度";
CM_ SG_ 2148827047 T2U_TMS_EnvTemp_1 "1号TMS环境温度";
CM_ SG_ 2148827047 M2P_TMSCoolingProtectMode_1_23 "1号TMS_制冷模式保护";
CM_ SG_ 2148827048 U2T_BMS_ControlMode_1 "BMS请求1号TMS设定模式";
CM_ SG_ 2148827048 T2U_TMS_RunState_1 "1号TMS运行状态";
CM_ SG_ 2148827048 T2U_TMS_FaultCode_1 "1号TMS故障码";
CM_ SG_ 2148827048 T2U_TMS_FaultLevel_1 "1号TMS故障码等级";
CM_ SG_ 2148827048 U2T_BMS_TmptSetPoint_1 "1号TMS BMS设定温度";
CM_ SG_ 2148827048 T2U_TMS_OutWaterTemp_1 "1号TMS出水温度";
CM_ SG_ 2148827048 T2U_TMS_BackWaterTemp_1 "1号TMS回水温度";
CM_ SG_ 2148827048 T2U_TMS_EnvTemp_1 "1号TMS环境温度";
CM_ SG_ 2148827048 M2P_TMSCoolingProtectMode_1_24 "1号TMS_制冷模式保护";
CM_ SG_ 2148827049 U2T_BMS_ControlMode_1 "BMS请求1号TMS设定模式";
CM_ SG_ 2148827049 T2U_TMS_RunState_1 "1号TMS运行状态";
CM_ SG_ 2148827049 T2U_TMS_FaultCode_1 "1号TMS故障码";
CM_ SG_ 2148827049 T2U_TMS_FaultLevel_1 "1号TMS故障码等级";
CM_ SG_ 2148827049 U2T_BMS_TmptSetPoint_1 "1号TMS BMS设定温度";
CM_ SG_ 2148827049 T2U_TMS_OutWaterTemp_1 "1号TMS出水温度";
CM_ SG_ 2148827049 T2U_TMS_BackWaterTemp_1 "1号TMS回水温度";
CM_ SG_ 2148827049 T2U_TMS_EnvTemp_1 "1号TMS环境温度";
CM_ SG_ 2148827049 M2P_TMSCoolingProtectMode_1_25 "1号TMS_制冷模式保护";
CM_ SG_ 2148827050 U2T_BMS_ControlMode_1 "BMS请求1号TMS设定模式";
CM_ SG_ 2148827050 T2U_TMS_RunState_1 "1号TMS运行状态";
CM_ SG_ 2148827050 T2U_TMS_FaultCode_1 "1号TMS故障码";
CM_ SG_ 2148827050 T2U_TMS_FaultLevel_1 "1号TMS故障码等级";
CM_ SG_ 2148827050 U2T_BMS_TmptSetPoint_1 "1号TMS BMS设定温度";
CM_ SG_ 2148827050 T2U_TMS_OutWaterTemp_1 "1号TMS出水温度";
CM_ SG_ 2148827050 T2U_TMS_BackWaterTemp_1 "1号TMS回水温度";
CM_ SG_ 2148827050 T2U_TMS_EnvTemp_1 "1号TMS环境温度";
CM_ SG_ 2148827050 M2P_TMSCoolingProtectMode_1_26 "1号TMS_制冷模式保护";
CM_ SG_ 2148827051 U2T_BMS_ControlMode_1 "BMS请求1号TMS设定模式";
CM_ SG_ 2148827051 T2U_TMS_RunState_1 "1号TMS运行状态";
CM_ SG_ 2148827051 T2U_TMS_FaultCode_1 "1号TMS故障码";
CM_ SG_ 2148827051 T2U_TMS_FaultLevel_1 "1号TMS故障码等级";
CM_ SG_ 2148827051 U2T_BMS_TmptSetPoint_1 "1号TMS BMS设定温度";
CM_ SG_ 2148827051 T2U_TMS_OutWaterTemp_1 "1号TMS出水温度";
CM_ SG_ 2148827051 T2U_TMS_BackWaterTemp_1 "1号TMS回水温度";
CM_ SG_ 2148827051 T2U_TMS_EnvTemp_1 "1号TMS环境温度";
CM_ SG_ 2148827051 M2P_TMSCoolingProtectMode_1_27 "1号TMS_制冷模式保护";
CM_ SG_ 2148827052 U2T_BMS_ControlMode_1 "BMS请求1号TMS设定模式";
CM_ SG_ 2148827052 T2U_TMS_RunState_1 "1号TMS运行状态";
CM_ SG_ 2148827052 T2U_TMS_FaultCode_1 "1号TMS故障码";
CM_ SG_ 2148827052 T2U_TMS_FaultLevel_1 "1号TMS故障码等级";
CM_ SG_ 2148827052 U2T_BMS_TmptSetPoint_1 "1号TMS BMS设定温度";
CM_ SG_ 2148827052 T2U_TMS_OutWaterTemp_1 "1号TMS出水温度";
CM_ SG_ 2148827052 T2U_TMS_BackWaterTemp_1 "1号TMS回水温度";
CM_ SG_ 2148827052 T2U_TMS_EnvTemp_1 "1号TMS环境温度";
CM_ SG_ 2148827052 M2P_TMSCoolingProtectMode_1_28 "1号TMS_制冷模式保护";
CM_ SG_ 2148827053 U2T_BMS_ControlMode_1 "BMS请求1号TMS设定模式";
CM_ SG_ 2148827053 T2U_TMS_RunState_1 "1号TMS运行状态";
CM_ SG_ 2148827053 T2U_TMS_FaultCode_1 "1号TMS故障码";
CM_ SG_ 2148827053 T2U_TMS_FaultLevel_1 "1号TMS故障码等级";
CM_ SG_ 2148827053 U2T_BMS_TmptSetPoint_1 "1号TMS BMS设定温度";
CM_ SG_ 2148827053 T2U_TMS_OutWaterTemp_1 "1号TMS出水温度";
CM_ SG_ 2148827053 T2U_TMS_BackWaterTemp_1 "1号TMS回水温度";
CM_ SG_ 2148827053 T2U_TMS_EnvTemp_1 "1号TMS环境温度";
CM_ SG_ 2148827053 M2P_TMSCoolingProtectMode_1_29 "1号TMS_制冷模式保护";
CM_ SG_ 2148827054 U2T_BMS_ControlMode_1 "BMS请求1号TMS设定模式";
CM_ SG_ 2148827054 T2U_TMS_RunState_1 "1号TMS运行状态";
CM_ SG_ 2148827054 T2U_TMS_FaultCode_1 "1号TMS故障码";
CM_ SG_ 2148827054 T2U_TMS_FaultLevel_1 "1号TMS故障码等级";
CM_ SG_ 2148827054 U2T_BMS_TmptSetPoint_1 "1号TMS BMS设定温度";
CM_ SG_ 2148827054 T2U_TMS_OutWaterTemp_1 "1号TMS出水温度";
CM_ SG_ 2148827054 T2U_TMS_BackWaterTemp_1 "1号TMS回水温度";
CM_ SG_ 2148827054 T2U_TMS_EnvTemp_1 "1号TMS环境温度";
CM_ SG_ 2148827054 M2P_TMSCoolingProtectMode_1_30 "1号TMS_制冷模式保护";
CM_ SG_ 2148827055 U2T_BMS_ControlMode_1 "BMS请求1号TMS设定模式";
CM_ SG_ 2148827055 T2U_TMS_RunState_1 "1号TMS运行状态";
CM_ SG_ 2148827055 T2U_TMS_FaultCode_1 "1号TMS故障码";
CM_ SG_ 2148827055 T2U_TMS_FaultLevel_1 "1号TMS故障码等级";
CM_ SG_ 2148827055 U2T_BMS_TmptSetPoint_1 "1号TMS BMS设定温度";
CM_ SG_ 2148827055 T2U_TMS_OutWaterTemp_1 "1号TMS出水温度";
CM_ SG_ 2148827055 T2U_TMS_BackWaterTemp_1 "1号TMS回水温度";
CM_ SG_ 2148827055 T2U_TMS_EnvTemp_1 "1号TMS环境温度";
CM_ SG_ 2148827055 M2P_TMSCoolingProtectMode_1_31 "1号TMS_制冷模式保护";
CM_ SG_ 2148892561 U2T_BMS_ControlMode_2 "BMS请求2号TMS设定模式";
CM_ SG_ 2148892561 T2U_TMS_RunState_2 "2号TMS运行状态";
CM_ SG_ 2148892561 T2U_TMS_FaultCode_2 "2号TMS故障码";
CM_ SG_ 2148892561 T2U_TMS_FaultLevel_2 "2号TMS故障码等级";
CM_ SG_ 2148892561 U2T_BMS_TmptSetPoint_2 "2号BMS设定温度";
CM_ SG_ 2148892561 T2U_TMS_OutWaterTemp_2 "2号TMS出水温度";
CM_ SG_ 2148892561 T2U_TMS_BackWaterTemp_2 "2号TMS回水温度";
CM_ SG_ 2148892561 T2U_TMS_EnvTemp_2 "2号TMS环境温度";
CM_ SG_ 2148892561 T2U_TMS_K2_HVRealyState_2 "预留";
CM_ SG_ 2148892561 M2P_TMS_OvrTmpLwFltLvl3_2_01 "2号TMS_制冷模式保护";
CM_ SG_ 2148892562 U2T_BMS_ControlMode_2 "BMS请求2号TMS设定模式";
CM_ SG_ 2148892562 T2U_TMS_RunState_2 "2号TMS运行状态";
CM_ SG_ 2148892562 T2U_TMS_FaultCode_2 "2号TMS故障码";
CM_ SG_ 2148892562 T2U_TMS_FaultLevel_2 "2号TMS故障码等级";
CM_ SG_ 2148892562 U2T_BMS_TmptSetPoint_2 "2号BMS设定温度";
CM_ SG_ 2148892562 T2U_TMS_OutWaterTemp_2 "2号TMS出水温度";
CM_ SG_ 2148892562 T2U_TMS_BackWaterTemp_2 "2号TMS回水温度";
CM_ SG_ 2148892562 T2U_TMS_EnvTemp_2 "2号TMS环境温度";
CM_ SG_ 2148892562 T2U_TMS_K2_HVRealyState_2 "预留";
CM_ SG_ 2148892562 M2P_TMS_OvrTmpLwFltLvl3_2_02 "2号TMS_制冷模式保护";
VAL_ 2148749671 CellHeatMode_Status 0 "非自加热模式" 1 "自加热模式" ;
VAL_ 2148749671 CellHeatMode_PermitStatus 0 "允许自加热" 1 "禁止自加热" ;
VAL_ 2148749672 CellHeatMode_Status 0 "非自加热模式" 1 "自加热模式" ;
VAL_ 2148749672 CellHeatMode_PermitStatus 0 "允许自加热" 1 "禁止自加热" ;
VAL_ 2148749673 CellHeatMode_Status 0 "非自加热模式" 1 "自加热模式" ;
VAL_ 2148749673 CellHeatMode_PermitStatus 0 "允许自加热" 1 "禁止自加热" ;
VAL_ 2148749674 CellHeatMode_Status 0 "非自加热模式" 1 "自加热模式" ;
VAL_ 2148749674 CellHeatMode_PermitStatus 0 "允许自加热" 1 "禁止自加热" ;
VAL_ 2148749675 CellHeatMode_Status 0 "非自加热模式" 1 "自加热模式" ;
VAL_ 2148749675 CellHeatMode_PermitStatus 0 "允许自加热" 1 "禁止自加热" ;
VAL_ 2148749676 CellHeatMode_Status 0 "非自加热模式" 1 "自加热模式" ;
VAL_ 2148749676 CellHeatMode_PermitStatus 0 "允许自加热" 1 "禁止自加热" ;
VAL_ 2148749677 CellHeatMode_Status 0 "非自加热模式" 1 "自加热模式" ;
VAL_ 2148749677 CellHeatMode_PermitStatus 0 "允许自加热" 1 "禁止自加热" ;
VAL_ 2148749678 CellHeatMode_Status 0 "非自加热模式" 1 "自加热模式" ;
VAL_ 2148749678 CellHeatMode_PermitStatus 0 "允许自加热" 1 "禁止自加热" ;
VAL_ 2148749679 CellHeatMode_Status 0 "非自加热模式" 1 "自加热模式" ;
VAL_ 2148749679 CellHeatMode_PermitStatus 0 "允许自加热" 1 "禁止自加热" ;
VAL_ 2148749680 CellHeatMode_Status 0 "非自加热模式" 1 "自加热模式" ;
VAL_ 2148749680 CellHeatMode_PermitStatus 0 "允许自加热" 1 "禁止自加热" ;
VAL_ 2148749681 CellHeatMode_Status 0 "非自加热模式" 1 "自加热模式" ;
VAL_ 2148749681 CellHeatMode_PermitStatus 0 "允许自加热" 1 "禁止自加热" ;
VAL_ 2148749682 CellHeatMode_Status 0 "非自加热模式" 1 "自加热模式" ;
VAL_ 2148749682 CellHeatMode_PermitStatus 0 "允许自加热" 1 "禁止自加热" ;
VAL_ 2148749683 CellHeatMode_Status 0 "非自加热模式" 1 "自加热模式" ;
VAL_ 2148749683 CellHeatMode_PermitStatus 0 "允许自加热" 1 "禁止自加热" ;
VAL_ 2148749684 CellHeatMode_Status 0 "非自加热模式" 1 "自加热模式" ;
VAL_ 2148749684 CellHeatMode_PermitStatus 0 "允许自加热" 1 "禁止自加热" ;
VAL_ 2148749685 CellHeatMode_Status 0 "非自加热模式" 1 "自加热模式" ;
VAL_ 2148749685 CellHeatMode_PermitStatus 0 "允许自加热" 1 "禁止自加热" ;
VAL_ 2148749686 CellHeatMode_Status 0 "非自加热模式" 1 "自加热模式" ;
VAL_ 2148749686 CellHeatMode_PermitStatus 0 "允许自加热" 1 "禁止自加热" ;
VAL_ 2148749687 CellHeatMode_Status 0 "非自加热模式" 1 "自加热模式" ;
VAL_ 2148749687 CellHeatMode_PermitStatus 0 "允许自加热" 1 "禁止自加热" ;
VAL_ 2148749688 CellHeatMode_Status 0 "非自加热模式" 1 "自加热模式" ;
VAL_ 2148749688 CellHeatMode_PermitStatus 0 "允许自加热" 1 "禁止自加热" ;
VAL_ 2148749689 CellHeatMode_Status 0 "非自加热模式" 1 "自加热模式" ;
VAL_ 2148749689 CellHeatMode_PermitStatus 0 "允许自加热" 1 "禁止自加热" ;
VAL_ 2148749690 CellHeatMode_Status 0 "非自加热模式" 1 "自加热模式" ;
VAL_ 2148749690 CellHeatMode_PermitStatus 0 "允许自加热" 1 "禁止自加热" ;
VAL_ 2148749691 CellHeatMode_Status 0 "非自加热模式" 1 "自加热模式" ;
VAL_ 2148749691 CellHeatMode_PermitStatus 0 "允许自加热" 1 "禁止自加热" ;
VAL_ 2148749692 CellHeatMode_Status 0 "非自加热模式" 1 "自加热模式" ;
VAL_ 2148749692 CellHeatMode_PermitStatus 0 "允许自加热" 1 "禁止自加热" ;
VAL_ 2148749693 CellHeatMode_Status 0 "非自加热模式" 1 "自加热模式" ;
VAL_ 2148749693 CellHeatMode_PermitStatus 0 "允许自加热" 1 "禁止自加热" ;
VAL_ 2148749694 CellHeatMode_Status 0 "非自加热模式" 1 "自加热模式" ;
VAL_ 2148749694 CellHeatMode_PermitStatus 0 "允许自加热" 1 "禁止自加热" ;
VAL_ 2148749695 CellHeatMode_Status 0 "非自加热模式" 1 "自加热模式" ;
VAL_ 2148749695 CellHeatMode_PermitStatus 0 "允许自加热" 1 "禁止自加热" ;
VAL_ 2148827025 U2T_BMS_ControlMode_1 0 "关机模式" 1 "制冷模式" 2 "加热模式" 3 "自循环模式" ;
VAL_ 2148827025 T2U_TMS_RunState_1 0 "关机模式" 1 "制冷模式" 2 "加热模式" 3 "自循环模式" ;
VAL_ 2148827025 T2U_TMS_FaultCode_1 0 "无故障" ;
VAL_ 2148827025 T2U_TMS_FaultLevel_1 0 "无效" 1 "1级故障" 2 "2级故障" 3 "3级故障" ;
VAL_ 2148827025 U2T_BMS_TmptSetPoint_1 255 "Invalid" ;
VAL_ 2148827025 T2U_TMS_OutWaterTemp_1 255 "无效" ;
VAL_ 2148827025 T2U_TMS_BackWaterTemp_1 255 "无效" ;
VAL_ 2148827025 T2U_TMS_EnvTemp_1 255 "无效" ;
VAL_ 2148827025 M2P_TMSCoolingProtectMode_1_01 0 "制冷模式正常" 1 "环境温度超过55℃制冷保护或环境温度低于-40℃制冷保护" ;
VAL_ 2148827026 U2T_BMS_ControlMode_1 0 "关机模式" 1 "制冷模式" 2 "加热模式" 3 "自循环模式" ;
VAL_ 2148827026 T2U_TMS_RunState_1 0 "关机模式" 1 "制冷模式" 2 "加热模式" 3 "自循环模式" ;
VAL_ 2148827026 T2U_TMS_FaultCode_1 0 "无故障" ;
VAL_ 2148827026 T2U_TMS_FaultLevel_1 0 "无效" 1 "1级故障" 2 "2级故障" 3 "3级故障" ;
VAL_ 2148827026 U2T_BMS_TmptSetPoint_1 255 "Invalid" ;
VAL_ 2148827026 T2U_TMS_OutWaterTemp_1 255 "无效" ;
VAL_ 2148827026 T2U_TMS_BackWaterTemp_1 255 "无效" ;
VAL_ 2148827026 T2U_TMS_EnvTemp_1 255 "无效" ;
VAL_ 2148827026 M2P_TMSCoolingProtectMode_1_02 0 "制冷模式正常" 1 "环境温度超过55℃制冷保护或环境温度低于-40℃制冷保护" ;
VAL_ 2148827027 U2T_BMS_ControlMode_1 0 "关机模式" 1 "制冷模式" 2 "加热模式" 3 "自循环模式" ;
VAL_ 2148827027 T2U_TMS_RunState_1 0 "关机模式" 1 "制冷模式" 2 "加热模式" 3 "自循环模式" ;
VAL_ 2148827027 T2U_TMS_FaultCode_1 0 "无故障" ;
VAL_ 2148827027 T2U_TMS_FaultLevel_1 0 "无效" 1 "1级故障" 2 "2级故障" 3 "3级故障" ;
VAL_ 2148827027 U2T_BMS_TmptSetPoint_1 255 "Invalid" ;
VAL_ 2148827027 T2U_TMS_OutWaterTemp_1 255 "无效" ;
VAL_ 2148827027 T2U_TMS_BackWaterTemp_1 255 "无效" ;
VAL_ 2148827027 T2U_TMS_EnvTemp_1 255 "无效" ;
VAL_ 2148827027 M2P_TMSCoolingProtectMode_1_03 0 "制冷模式正常" 1 "环境温度超过55℃制冷保护或环境温度低于-40℃制冷保护" ;
VAL_ 2148827028 U2T_BMS_ControlMode_1 0 "关机模式" 1 "制冷模式" 2 "加热模式" 3 "自循环模式" ;
VAL_ 2148827028 T2U_TMS_RunState_1 0 "关机模式" 1 "制冷模式" 2 "加热模式" 3 "自循环模式" ;
VAL_ 2148827028 T2U_TMS_FaultCode_1 0 "无故障" ;
VAL_ 2148827028 T2U_TMS_FaultLevel_1 0 "无效" 1 "1级故障" 2 "2级故障" 3 "3级故障" ;
VAL_ 2148827028 U2T_BMS_TmptSetPoint_1 255 "Invalid" ;
VAL_ 2148827028 T2U_TMS_OutWaterTemp_1 255 "无效" ;
VAL_ 2148827028 T2U_TMS_BackWaterTemp_1 255 "无效" ;
VAL_ 2148827028 T2U_TMS_EnvTemp_1 255 "无效" ;
VAL_ 2148827028 M2P_TMSCoolingProtectMode_1_04 0 "制冷模式正常" 1 "环境温度超过55℃制冷保护或环境温度低于-40℃制冷保护" ;
VAL_ 2148827029 U2T_BMS_ControlMode_1 0 "关机模式" 1 "制冷模式" 2 "加热模式" 3 "自循环模式" ;
VAL_ 2148827029 T2U_TMS_RunState_1 0 "关机模式" 1 "制冷模式" 2 "加热模式" 3 "自循环模式" ;
VAL_ 2148827029 T2U_TMS_FaultCode_1 0 "无故障" ;
VAL_ 2148827029 T2U_TMS_FaultLevel_1 0 "无效" 1 "1级故障" 2 "2级故障" 3 "3级故障" ;
VAL_ 2148827029 U2T_BMS_TmptSetPoint_1 255 "Invalid" ;
VAL_ 2148827029 T2U_TMS_OutWaterTemp_1 255 "无效" ;
VAL_ 2148827029 T2U_TMS_BackWaterTemp_1 255 "无效" ;
VAL_ 2148827029 T2U_TMS_EnvTemp_1 255 "无效" ;
VAL_ 2148827029 M2P_TMSCoolingProtectMode_1_05 0 "制冷模式正常" 1 "环境温度超过55℃制冷保护或环境温度低于-40℃制冷保护" ;
VAL_ 2148827030 U2T_BMS_ControlMode_1 0 "关机模式" 1 "制冷模式" 2 "加热模式" 3 "自循环模式" ;
VAL_ 2148827030 T2U_TMS_RunState_1 0 "关机模式" 1 "制冷模式" 2 "加热模式" 3 "自循环模式" ;
VAL_ 2148827030 T2U_TMS_FaultCode_1 0 "无故障" ;
VAL_ 2148827030 T2U_TMS_FaultLevel_1 0 "无效" 1 "1级故障" 2 "2级故障" 3 "3级故障" ;
VAL_ 2148827030 U2T_BMS_TmptSetPoint_1 255 "Invalid" ;
VAL_ 2148827030 T2U_TMS_OutWaterTemp_1 255 "无效" ;
VAL_ 2148827030 T2U_TMS_BackWaterTemp_1 255 "无效" ;
VAL_ 2148827030 T2U_TMS_EnvTemp_1 255 "无效" ;
VAL_ 2148827030 M2P_TMSCoolingProtectMode_1_06 0 "制冷模式正常" 1 "环境温度超过55℃制冷保护或环境温度低于-40℃制冷保护" ;
VAL_ 2148827031 U2T_BMS_ControlMode_1 0 "关机模式" 1 "制冷模式" 2 "加热模式" 3 "自循环模式" ;
VAL_ 2148827031 T2U_TMS_RunState_1 0 "关机模式" 1 "制冷模式" 2 "加热模式" 3 "自循环模式" ;
VAL_ 2148827031 T2U_TMS_FaultCode_1 0 "无故障" ;
VAL_ 2148827031 T2U_TMS_FaultLevel_1 0 "无效" 1 "1级故障" 2 "2级故障" 3 "3级故障" ;
VAL_ 2148827031 U2T_BMS_TmptSetPoint_1 255 "Invalid" ;
VAL_ 2148827031 T2U_TMS_OutWaterTemp_1 255 "无效" ;
VAL_ 2148827031 T2U_TMS_BackWaterTemp_1 255 "无效" ;
VAL_ 2148827031 T2U_TMS_EnvTemp_1 255 "无效" ;
VAL_ 2148827031 M2P_TMSCoolingProtectMode_1_07 0 "制冷模式正常" 1 "环境温度超过55℃制冷保护或环境温度低于-40℃制冷保护" ;
VAL_ 2148827032 U2T_BMS_ControlMode_1 0 "关机模式" 1 "制冷模式" 2 "加热模式" 3 "自循环模式" ;
VAL_ 2148827032 T2U_TMS_RunState_1 0 "关机模式" 1 "制冷模式" 2 "加热模式" 3 "自循环模式" ;
VAL_ 2148827032 T2U_TMS_FaultCode_1 0 "无故障" ;
VAL_ 2148827032 T2U_TMS_FaultLevel_1 0 "无效" 1 "1级故障" 2 "2级故障" 3 "3级故障" ;
VAL_ 2148827032 U2T_BMS_TmptSetPoint_1 255 "Invalid" ;
VAL_ 2148827032 T2U_TMS_OutWaterTemp_1 255 "无效" ;
VAL_ 2148827032 T2U_TMS_BackWaterTemp_1 255 "无效" ;
VAL_ 2148827032 T2U_TMS_EnvTemp_1 255 "无效" ;
VAL_ 2148827032 M2P_TMSCoolingProtectMode_1_08 0 "制冷模式正常" 1 "环境温度超过55℃制冷保护或环境温度低于-40℃制冷保护" ;
VAL_ 2148827033 U2T_BMS_ControlMode_1 0 "关机模式" 1 "制冷模式" 2 "加热模式" 3 "自循环模式" ;
VAL_ 2148827033 T2U_TMS_RunState_1 0 "关机模式" 1 "制冷模式" 2 "加热模式" 3 "自循环模式" ;
VAL_ 2148827033 T2U_TMS_FaultCode_1 0 "无故障" ;
VAL_ 2148827033 T2U_TMS_FaultLevel_1 0 "无效" 1 "1级故障" 2 "2级故障" 3 "3级故障" ;
VAL_ 2148827033 U2T_BMS_TmptSetPoint_1 255 "Invalid" ;
VAL_ 2148827033 T2U_TMS_OutWaterTemp_1 255 "无效" ;
VAL_ 2148827033 T2U_TMS_BackWaterTemp_1 255 "无效" ;
VAL_ 2148827033 T2U_TMS_EnvTemp_1 255 "无效" ;
VAL_ 2148827033 M2P_TMSCoolingProtectMode_1_09 0 "制冷模式正常" 1 "环境温度超过55℃制冷保护或环境温度低于-40℃制冷保护" ;
VAL_ 2148827034 U2T_BMS_ControlMode_1 0 "关机模式" 1 "制冷模式" 2 "加热模式" 3 "自循环模式" ;
VAL_ 2148827034 T2U_TMS_RunState_1 0 "关机模式" 1 "制冷模式" 2 "加热模式" 3 "自循环模式" ;
VAL_ 2148827034 T2U_TMS_FaultCode_1 0 "无故障" ;
VAL_ 2148827034 T2U_TMS_FaultLevel_1 0 "无效" 1 "1级故障" 2 "2级故障" 3 "3级故障" ;
VAL_ 2148827034 U2T_BMS_TmptSetPoint_1 255 "Invalid" ;
VAL_ 2148827034 T2U_TMS_OutWaterTemp_1 255 "无效" ;
VAL_ 2148827034 T2U_TMS_BackWaterTemp_1 255 "无效" ;
VAL_ 2148827034 T2U_TMS_EnvTemp_1 255 "无效" ;
VAL_ 2148827034 M2P_TMSCoolingProtectMode_1_10 0 "制冷模式正常" 1 "环境温度超过55℃制冷保护或环境温度低于-40℃制冷保护" ;
VAL_ 2148827035 U2T_BMS_ControlMode_1 0 "关机模式" 1 "制冷模式" 2 "加热模式" 3 "自循环模式" ;
VAL_ 2148827035 T2U_TMS_RunState_1 0 "关机模式" 1 "制冷模式" 2 "加热模式" 3 "自循环模式" ;
VAL_ 2148827035 T2U_TMS_FaultCode_1 0 "无故障" ;
VAL_ 2148827035 T2U_TMS_FaultLevel_1 0 "无效" 1 "1级故障" 2 "2级故障" 3 "3级故障" ;
VAL_ 2148827035 U2T_BMS_TmptSetPoint_1 255 "Invalid" ;
VAL_ 2148827035 T2U_TMS_OutWaterTemp_1 255 "无效" ;
VAL_ 2148827035 T2U_TMS_BackWaterTemp_1 255 "无效" ;
VAL_ 2148827035 T2U_TMS_EnvTemp_1 255 "无效" ;
VAL_ 2148827035 M2P_TMSCoolingProtectMode_1_11 0 "制冷模式正常" 1 "环境温度超过55℃制冷保护或环境温度低于-40℃制冷保护" ;
VAL_ 2148827036 U2T_BMS_ControlMode_1 0 "关机模式" 1 "制冷模式" 2 "加热模式" 3 "自循环模式" ;
VAL_ 2148827036 T2U_TMS_RunState_1 0 "关机模式" 1 "制冷模式" 2 "加热模式" 3 "自循环模式" ;
VAL_ 2148827036 T2U_TMS_FaultCode_1 0 "无故障" ;
VAL_ 2148827036 T2U_TMS_FaultLevel_1 0 "无效" 1 "1级故障" 2 "2级故障" 3 "3级故障" ;
VAL_ 2148827036 U2T_BMS_TmptSetPoint_1 255 "Invalid" ;
VAL_ 2148827036 T2U_TMS_OutWaterTemp_1 255 "无效" ;
VAL_ 2148827036 T2U_TMS_BackWaterTemp_1 255 "无效" ;
VAL_ 2148827036 T2U_TMS_EnvTemp_1 255 "无效" ;
VAL_ 2148827036 M2P_TMSCoolingProtectMode_1_12 0 "制冷模式正常" 1 "环境温度超过55℃制冷保护或环境温度低于-40℃制冷保护" ;
VAL_ 2148827037 U2T_BMS_ControlMode_1 0 "关机模式" 1 "制冷模式" 2 "加热模式" 3 "自循环模式" ;
VAL_ 2148827037 T2U_TMS_RunState_1 0 "关机模式" 1 "制冷模式" 2 "加热模式" 3 "自循环模式" ;
VAL_ 2148827037 T2U_TMS_FaultCode_1 0 "无故障" ;
VAL_ 2148827037 T2U_TMS_FaultLevel_1 0 "无效" 1 "1级故障" 2 "2级故障" 3 "3级故障" ;
VAL_ 2148827037 U2T_BMS_TmptSetPoint_1 255 "Invalid" ;
VAL_ 2148827037 T2U_TMS_OutWaterTemp_1 255 "无效" ;
VAL_ 2148827037 T2U_TMS_BackWaterTemp_1 255 "无效" ;
VAL_ 2148827037 T2U_TMS_EnvTemp_1 255 "无效" ;
VAL_ 2148827037 M2P_TMSCoolingProtectMode_1_13 0 "制冷模式正常" 1 "环境温度超过55℃制冷保护或环境温度低于-40℃制冷保护" ;
VAL_ 2148827038 U2T_BMS_ControlMode_1 0 "关机模式" 1 "制冷模式" 2 "加热模式" 3 "自循环模式" ;
VAL_ 2148827038 T2U_TMS_RunState_1 0 "关机模式" 1 "制冷模式" 2 "加热模式" 3 "自循环模式" ;
VAL_ 2148827038 T2U_TMS_FaultCode_1 0 "无故障" ;
VAL_ 2148827038 T2U_TMS_FaultLevel_1 0 "无效" 1 "1级故障" 2 "2级故障" 3 "3级故障" ;
VAL_ 2148827038 U2T_BMS_TmptSetPoint_1 255 "Invalid" ;
VAL_ 2148827038 T2U_TMS_OutWaterTemp_1 255 "无效" ;
VAL_ 2148827038 T2U_TMS_BackWaterTemp_1 255 "无效" ;
VAL_ 2148827038 T2U_TMS_EnvTemp_1 255 "无效" ;
VAL_ 2148827038 M2P_TMSCoolingProtectMode_1_14 0 "制冷模式正常" 1 "环境温度超过55℃制冷保护或环境温度低于-40℃制冷保护" ;
VAL_ 2148827039 U2T_BMS_ControlMode_1 0 "关机模式" 1 "制冷模式" 2 "加热模式" 3 "自循环模式" ;
VAL_ 2148827039 T2U_TMS_RunState_1 0 "关机模式" 1 "制冷模式" 2 "加热模式" 3 "自循环模式" ;
VAL_ 2148827039 T2U_TMS_FaultCode_1 0 "无故障" ;
VAL_ 2148827039 T2U_TMS_FaultLevel_1 0 "无效" 1 "1级故障" 2 "2级故障" 3 "3级故障" ;
VAL_ 2148827039 U2T_BMS_TmptSetPoint_1 255 "Invalid" ;
VAL_ 2148827039 T2U_TMS_OutWaterTemp_1 255 "无效" ;
VAL_ 2148827039 T2U_TMS_BackWaterTemp_1 255 "无效" ;
VAL_ 2148827039 T2U_TMS_EnvTemp_1 255 "无效" ;
VAL_ 2148827039 M2P_TMSCoolingProtectMode_1_15 0 "制冷模式正常" 1 "环境温度超过55℃制冷保护或环境温度低于-40℃制冷保护" ;
VAL_ 2148827040 U2T_BMS_ControlMode_1 0 "关机模式" 1 "制冷模式" 2 "加热模式" 3 "自循环模式" ;
VAL_ 2148827040 T2U_TMS_RunState_1 0 "关机模式" 1 "制冷模式" 2 "加热模式" 3 "自循环模式" ;
VAL_ 2148827040 T2U_TMS_FaultCode_1 0 "无故障" ;
VAL_ 2148827040 T2U_TMS_FaultLevel_1 0 "无效" 1 "1级故障" 2 "2级故障" 3 "3级故障" ;
VAL_ 2148827040 U2T_BMS_TmptSetPoint_1 255 "Invalid" ;
VAL_ 2148827040 T2U_TMS_OutWaterTemp_1 255 "无效" ;
VAL_ 2148827040 T2U_TMS_BackWaterTemp_1 255 "无效" ;
VAL_ 2148827040 T2U_TMS_EnvTemp_1 255 "无效" ;
VAL_ 2148827040 M2P_TMSCoolingProtectMode_1_16 0 "制冷模式正常" 1 "环境温度超过55℃制冷保护或环境温度低于-40℃制冷保护" ;
VAL_ 2148827041 U2T_BMS_ControlMode_1 0 "关机模式" 1 "制冷模式" 2 "加热模式" 3 "自循环模式" ;
VAL_ 2148827041 T2U_TMS_RunState_1 0 "关机模式" 1 "制冷模式" 2 "加热模式" 3 "自循环模式" ;
VAL_ 2148827041 T2U_TMS_FaultCode_1 0 "无故障" ;
VAL_ 2148827041 T2U_TMS_FaultLevel_1 0 "无效" 1 "1级故障" 2 "2级故障" 3 "3级故障" ;
VAL_ 2148827041 U2T_BMS_TmptSetPoint_1 255 "Invalid" ;
VAL_ 2148827041 T2U_TMS_OutWaterTemp_1 255 "无效" ;
VAL_ 2148827041 T2U_TMS_BackWaterTemp_1 255 "无效" ;
VAL_ 2148827041 T2U_TMS_EnvTemp_1 255 "无效" ;
VAL_ 2148827041 M2P_TMSCoolingProtectMode_1_17 0 "制冷模式正常" 1 "环境温度超过55℃制冷保护或环境温度低于-40℃制冷保护" ;
VAL_ 2148827042 U2T_BMS_ControlMode_1 0 "关机模式" 1 "制冷模式" 2 "加热模式" 3 "自循环模式" ;
VAL_ 2148827042 T2U_TMS_RunState_1 0 "关机模式" 1 "制冷模式" 2 "加热模式" 3 "自循环模式" ;
VAL_ 2148827042 T2U_TMS_FaultCode_1 0 "无故障" ;
VAL_ 2148827042 T2U_TMS_FaultLevel_1 0 "无效" 1 "1级故障" 2 "2级故障" 3 "3级故障" ;
VAL_ 2148827042 U2T_BMS_TmptSetPoint_1 255 "Invalid" ;
VAL_ 2148827042 T2U_TMS_OutWaterTemp_1 255 "无效" ;
VAL_ 2148827042 T2U_TMS_BackWaterTemp_1 255 "无效" ;
VAL_ 2148827042 T2U_TMS_EnvTemp_1 255 "无效" ;
VAL_ 2148827042 M2P_TMSCoolingProtectMode_1_18 0 "制冷模式正常" 1 "环境温度超过55℃制冷保护或环境温度低于-40℃制冷保护" ;
VAL_ 2148827043 U2T_BMS_ControlMode_1 0 "关机模式" 1 "制冷模式" 2 "加热模式" 3 "自循环模式" ;
VAL_ 2148827043 T2U_TMS_RunState_1 0 "关机模式" 1 "制冷模式" 2 "加热模式" 3 "自循环模式" ;
VAL_ 2148827043 T2U_TMS_FaultCode_1 0 "无故障" ;
VAL_ 2148827043 T2U_TMS_FaultLevel_1 0 "无效" 1 "1级故障" 2 "2级故障" 3 "3级故障" ;
VAL_ 2148827043 U2T_BMS_TmptSetPoint_1 255 "Invalid" ;
VAL_ 2148827043 T2U_TMS_OutWaterTemp_1 255 "无效" ;
VAL_ 2148827043 T2U_TMS_BackWaterTemp_1 255 "无效" ;
VAL_ 2148827043 T2U_TMS_EnvTemp_1 255 "无效" ;
VAL_ 2148827043 M2P_TMSCoolingProtectMode_1_19 0 "制冷模式正常" 1 "环境温度超过55℃制冷保护或环境温度低于-40℃制冷保护" ;
VAL_ 2148827044 U2T_BMS_ControlMode_1 0 "关机模式" 1 "制冷模式" 2 "加热模式" 3 "自循环模式" ;
VAL_ 2148827044 T2U_TMS_RunState_1 0 "关机模式" 1 "制冷模式" 2 "加热模式" 3 "自循环模式" ;
VAL_ 2148827044 T2U_TMS_FaultCode_1 0 "无故障" ;
VAL_ 2148827044 T2U_TMS_FaultLevel_1 0 "无效" 1 "1级故障" 2 "2级故障" 3 "3级故障" ;
VAL_ 2148827044 U2T_BMS_TmptSetPoint_1 255 "Invalid" ;
VAL_ 2148827044 T2U_TMS_OutWaterTemp_1 255 "无效" ;
VAL_ 2148827044 T2U_TMS_BackWaterTemp_1 255 "无效" ;
VAL_ 2148827044 T2U_TMS_EnvTemp_1 255 "无效" ;
VAL_ 2148827044 M2P_TMSCoolingProtectMode_1_20 0 "制冷模式正常" 1 "环境温度超过55℃制冷保护或环境温度低于-40℃制冷保护" ;
VAL_ 2148827045 U2T_BMS_ControlMode_1 0 "关机模式" 1 "制冷模式" 2 "加热模式" 3 "自循环模式" ;
VAL_ 2148827045 T2U_TMS_RunState_1 0 "关机模式" 1 "制冷模式" 2 "加热模式" 3 "自循环模式" ;
VAL_ 2148827045 T2U_TMS_FaultCode_1 0 "无故障" ;
VAL_ 2148827045 T2U_TMS_FaultLevel_1 0 "无效" 1 "1级故障" 2 "2级故障" 3 "3级故障" ;
VAL_ 2148827045 U2T_BMS_TmptSetPoint_1 255 "Invalid" ;
VAL_ 2148827045 T2U_TMS_OutWaterTemp_1 255 "无效" ;
VAL_ 2148827045 T2U_TMS_BackWaterTemp_1 255 "无效" ;
VAL_ 2148827045 T2U_TMS_EnvTemp_1 255 "无效" ;
VAL_ 2148827045 M2P_TMSCoolingProtectMode_1_21 0 "制冷模式正常" 1 "环境温度超过55℃制冷保护或环境温度低于-40℃制冷保护" ;
VAL_ 2148827046 U2T_BMS_ControlMode_1 0 "关机模式" 1 "制冷模式" 2 "加热模式" 3 "自循环模式" ;
VAL_ 2148827046 T2U_TMS_RunState_1 0 "关机模式" 1 "制冷模式" 2 "加热模式" 3 "自循环模式" ;
VAL_ 2148827046 T2U_TMS_FaultCode_1 0 "无故障" ;
VAL_ 2148827046 T2U_TMS_FaultLevel_1 0 "无效" 1 "1级故障" 2 "2级故障" 3 "3级故障" ;
VAL_ 2148827046 U2T_BMS_TmptSetPoint_1 255 "Invalid" ;
VAL_ 2148827046 T2U_TMS_OutWaterTemp_1 255 "无效" ;
VAL_ 2148827046 T2U_TMS_BackWaterTemp_1 255 "无效" ;
VAL_ 2148827046 T2U_TMS_EnvTemp_1 255 "无效" ;
VAL_ 2148827046 M2P_TMSCoolingProtectMode_1_22 0 "制冷模式正常" 1 "环境温度超过55℃制冷保护或环境温度低于-40℃制冷保护" ;
VAL_ 2148827047 U2T_BMS_ControlMode_1 0 "关机模式" 1 "制冷模式" 2 "加热模式" 3 "自循环模式" ;
VAL_ 2148827047 T2U_TMS_RunState_1 0 "关机模式" 1 "制冷模式" 2 "加热模式" 3 "自循环模式" ;
VAL_ 2148827047 T2U_TMS_FaultCode_1 0 "无故障" ;
VAL_ 2148827047 T2U_TMS_FaultLevel_1 0 "无效" 1 "1级故障" 2 "2级故障" 3 "3级故障" ;
VAL_ 2148827047 U2T_BMS_TmptSetPoint_1 255 "Invalid" ;
VAL_ 2148827047 T2U_TMS_OutWaterTemp_1 255 "无效" ;
VAL_ 2148827047 T2U_TMS_BackWaterTemp_1 255 "无效" ;
VAL_ 2148827047 T2U_TMS_EnvTemp_1 255 "无效" ;
VAL_ 2148827047 M2P_TMSCoolingProtectMode_1_23 0 "制冷模式正常" 1 "环境温度超过55℃制冷保护或环境温度低于-40℃制冷保护" ;
VAL_ 2148827048 U2T_BMS_ControlMode_1 0 "关机模式" 1 "制冷模式" 2 "加热模式" 3 "自循环模式" ;
VAL_ 2148827048 T2U_TMS_RunState_1 0 "关机模式" 1 "制冷模式" 2 "加热模式" 3 "自循环模式" ;
VAL_ 2148827048 T2U_TMS_FaultCode_1 0 "无故障" ;
VAL_ 2148827048 T2U_TMS_FaultLevel_1 0 "无效" 1 "1级故障" 2 "2级故障" 3 "3级故障" ;
VAL_ 2148827048 U2T_BMS_TmptSetPoint_1 255 "Invalid" ;
VAL_ 2148827048 T2U_TMS_OutWaterTemp_1 255 "无效" ;
VAL_ 2148827048 T2U_TMS_BackWaterTemp_1 255 "无效" ;
VAL_ 2148827048 T2U_TMS_EnvTemp_1 255 "无效" ;
VAL_ 2148827048 M2P_TMSCoolingProtectMode_1_24 0 "制冷模式正常" 1 "环境温度超过55℃制冷保护或环境温度低于-40℃制冷保护" ;
VAL_ 2148827049 U2T_BMS_ControlMode_1 0 "关机模式" 1 "制冷模式" 2 "加热模式" 3 "自循环模式" ;
VAL_ 2148827049 T2U_TMS_RunState_1 0 "关机模式" 1 "制冷模式" 2 "加热模式" 3 "自循环模式" ;
VAL_ 2148827049 T2U_TMS_FaultCode_1 0 "无故障" ;
VAL_ 2148827049 T2U_TMS_FaultLevel_1 0 "无效" 1 "1级故障" 2 "2级故障" 3 "3级故障" ;
VAL_ 2148827049 U2T_BMS_TmptSetPoint_1 255 "Invalid" ;
VAL_ 2148827049 T2U_TMS_OutWaterTemp_1 255 "无效" ;
VAL_ 2148827049 T2U_TMS_BackWaterTemp_1 255 "无效" ;
VAL_ 2148827049 T2U_TMS_EnvTemp_1 255 "无效" ;
VAL_ 2148827049 M2P_TMSCoolingProtectMode_1_25 0 "制冷模式正常" 1 "环境温度超过55℃制冷保护或环境温度低于-40℃制冷保护" ;
VAL_ 2148827050 U2T_BMS_ControlMode_1 0 "关机模式" 1 "制冷模式" 2 "加热模式" 3 "自循环模式" ;
VAL_ 2148827050 T2U_TMS_RunState_1 0 "关机模式" 1 "制冷模式" 2 "加热模式" 3 "自循环模式" ;
VAL_ 2148827050 T2U_TMS_FaultCode_1 0 "无故障" ;
VAL_ 2148827050 T2U_TMS_FaultLevel_1 0 "无效" 1 "1级故障" 2 "2级故障" 3 "3级故障" ;
VAL_ 2148827050 U2T_BMS_TmptSetPoint_1 255 "Invalid" ;
VAL_ 2148827050 T2U_TMS_OutWaterTemp_1 255 "无效" ;
VAL_ 2148827050 T2U_TMS_BackWaterTemp_1 255 "无效" ;
VAL_ 2148827050 T2U_TMS_EnvTemp_1 255 "无效" ;
VAL_ 2148827050 M2P_TMSCoolingProtectMode_1_26 0 "制冷模式正常" 1 "环境温度超过55℃制冷保护或环境温度低于-40℃制冷保护" ;
VAL_ 2148827051 U2T_BMS_ControlMode_1 0 "关机模式" 1 "制冷模式" 2 "加热模式" 3 "自循环模式" ;
VAL_ 2148827051 T2U_TMS_RunState_1 0 "关机模式" 1 "制冷模式" 2 "加热模式" 3 "自循环模式" ;
VAL_ 2148827051 T2U_TMS_FaultCode_1 0 "无故障" ;
VAL_ 2148827051 T2U_TMS_FaultLevel_1 0 "无效" 1 "1级故障" 2 "2级故障" 3 "3级故障" ;
VAL_ 2148827051 U2T_BMS_TmptSetPoint_1 255 "Invalid" ;
VAL_ 2148827051 T2U_TMS_OutWaterTemp_1 255 "无效" ;
VAL_ 2148827051 T2U_TMS_BackWaterTemp_1 255 "无效" ;
VAL_ 2148827051 T2U_TMS_EnvTemp_1 255 "无效" ;
VAL_ 2148827051 M2P_TMSCoolingProtectMode_1_27 0 "制冷模式正常" 1 "环境温度超过55℃制冷保护或环境温度低于-40℃制冷保护" ;
VAL_ 2148827052 U2T_BMS_ControlMode_1 0 "关机模式" 1 "制冷模式" 2 "加热模式" 3 "自循环模式" ;
VAL_ 2148827052 T2U_TMS_RunState_1 0 "关机模式" 1 "制冷模式" 2 "加热模式" 3 "自循环模式" ;
VAL_ 2148827052 T2U_TMS_FaultCode_1 0 "无故障" ;
VAL_ 2148827052 T2U_TMS_FaultLevel_1 0 "无效" 1 "1级故障" 2 "2级故障" 3 "3级故障" ;
VAL_ 2148827052 U2T_BMS_TmptSetPoint_1 255 "Invalid" ;
VAL_ 2148827052 T2U_TMS_OutWaterTemp_1 255 "无效" ;
VAL_ 2148827052 T2U_TMS_BackWaterTemp_1 255 "无效" ;
VAL_ 2148827052 T2U_TMS_EnvTemp_1 255 "无效" ;
VAL_ 2148827052 M2P_TMSCoolingProtectMode_1_28 0 "制冷模式正常" 1 "环境温度超过55℃制冷保护或环境温度低于-40℃制冷保护" ;
VAL_ 2148827053 U2T_BMS_ControlMode_1 0 "关机模式" 1 "制冷模式" 2 "加热模式" 3 "自循环模式" ;
VAL_ 2148827053 T2U_TMS_RunState_1 0 "关机模式" 1 "制冷模式" 2 "加热模式" 3 "自循环模式" ;
VAL_ 2148827053 T2U_TMS_FaultCode_1 0 "无故障" ;
VAL_ 2148827053 T2U_TMS_FaultLevel_1 0 "无效" 1 "1级故障" 2 "2级故障" 3 "3级故障" ;
VAL_ 2148827053 U2T_BMS_TmptSetPoint_1 255 "Invalid" ;
VAL_ 2148827053 T2U_TMS_OutWaterTemp_1 255 "无效" ;
VAL_ 2148827053 T2U_TMS_BackWaterTemp_1 255 "无效" ;
VAL_ 2148827053 T2U_TMS_EnvTemp_1 255 "无效" ;
VAL_ 2148827053 M2P_TMSCoolingProtectMode_1_29 0 "制冷模式正常" 1 "环境温度超过55℃制冷保护或环境温度低于-40℃制冷保护" ;
VAL_ 2148827054 U2T_BMS_ControlMode_1 0 "关机模式" 1 "制冷模式" 2 "加热模式" 3 "自循环模式" ;
VAL_ 2148827054 T2U_TMS_RunState_1 0 "关机模式" 1 "制冷模式" 2 "加热模式" 3 "自循环模式" ;
VAL_ 2148827054 T2U_TMS_FaultCode_1 0 "无故障" ;
VAL_ 2148827054 T2U_TMS_FaultLevel_1 0 "无效" 1 "1级故障" 2 "2级故障" 3 "3级故障" ;
VAL_ 2148827054 U2T_BMS_TmptSetPoint_1 255 "Invalid" ;
VAL_ 2148827054 T2U_TMS_OutWaterTemp_1 255 "无效" ;
VAL_ 2148827054 T2U_TMS_BackWaterTemp_1 255 "无效" ;
VAL_ 2148827054 T2U_TMS_EnvTemp_1 255 "无效" ;
VAL_ 2148827054 M2P_TMSCoolingProtectMode_1_30 0 "制冷模式正常" 1 "环境温度超过55℃制冷保护或环境温度低于-40℃制冷保护" ;
VAL_ 2148827055 U2T_BMS_ControlMode_1 0 "关机模式" 1 "制冷模式" 2 "加热模式" 3 "自循环模式" ;
VAL_ 2148827055 T2U_TMS_RunState_1 0 "关机模式" 1 "制冷模式" 2 "加热模式" 3 "自循环模式" ;
VAL_ 2148827055 T2U_TMS_FaultCode_1 0 "无故障" ;
VAL_ 2148827055 T2U_TMS_FaultLevel_1 0 "无效" 1 "1级故障" 2 "2级故障" 3 "3级故障" ;
VAL_ 2148827055 U2T_BMS_TmptSetPoint_1 255 "Invalid" ;
VAL_ 2148827055 T2U_TMS_OutWaterTemp_1 255 "无效" ;
VAL_ 2148827055 T2U_TMS_BackWaterTemp_1 255 "无效" ;
VAL_ 2148827055 T2U_TMS_EnvTemp_1 255 "无效" ;
VAL_ 2148827055 M2P_TMSCoolingProtectMode_1_31 0 "制冷模式正常" 1 "环境温度超过55℃制冷保护或环境温度低于-40℃制冷保护" ;
VAL_ 2148892561 U2T_BMS_ControlMode_2 0 "关机模式" 1 "制冷模式" 2 "加热模式" 3 "自循环模式" ;
VAL_ 2148892561 T2U_TMS_RunState_2 0 "关机模式" 1 "制冷模式" 2 "加热模式" 3 "自循环模式" ;
VAL_ 2148892561 T2U_TMS_FaultCode_2 0 "无故障" ;
VAL_ 2148892561 T2U_TMS_FaultLevel_2 0 "无效" 1 "1级故障" 2 "2级故障" 3 "3级故障" ;
VAL_ 2148892561 U2T_BMS_TmptSetPoint_2 255 "Invalid" ;
VAL_ 2148892561 T2U_TMS_OutWaterTemp_2 255 "无效" ;
VAL_ 2148892561 T2U_TMS_BackWaterTemp_2 255 "无效" ;
VAL_ 2148892561 T2U_TMS_EnvTemp_2 255 "无效" ;
VAL_ 2148892561 M2P_TMS_OvrTmpLwFltLvl3_2_01 0 "制冷模式正常" 1 "环境温度超过55℃制冷保护或环境温度低于-40℃制冷保护" ;
VAL_ 2148892562 U2T_BMS_ControlMode_2 0 "关机模式" 1 "制冷模式" 2 "加热模式" 3 "自循环模式" ;
VAL_ 2148892562 T2U_TMS_RunState_2 0 "关机模式" 1 "制冷模式" 2 "加热模式" 3 "自循环模式" ;
VAL_ 2148892562 T2U_TMS_FaultCode_2 0 "无故障" ;
VAL_ 2148892562 T2U_TMS_FaultLevel_2 0 "无效" 1 "1级故障" 2 "2级故障" 3 "3级故障" ;
VAL_ 2148892562 U2T_BMS_TmptSetPoint_2 255 "Invalid" ;
VAL_ 2148892562 T2U_TMS_OutWaterTemp_2 255 "无效" ;
VAL_ 2148892562 T2U_TMS_BackWaterTemp_2 255 "无效" ;
VAL_ 2148892562 T2U_TMS_EnvTemp_2 255 "无效" ;
VAL_ 2148892562 M2P_TMS_OvrTmpLwFltLvl3_2_02 0 "制冷模式正常" 1 "环境温度超过55℃制冷保护或环境温度低于-40℃制冷保护" ;
VERSION ""

NS_ :

BS_:

BU_: MBMU PC SBMU IMM ETH DCDC LEMS

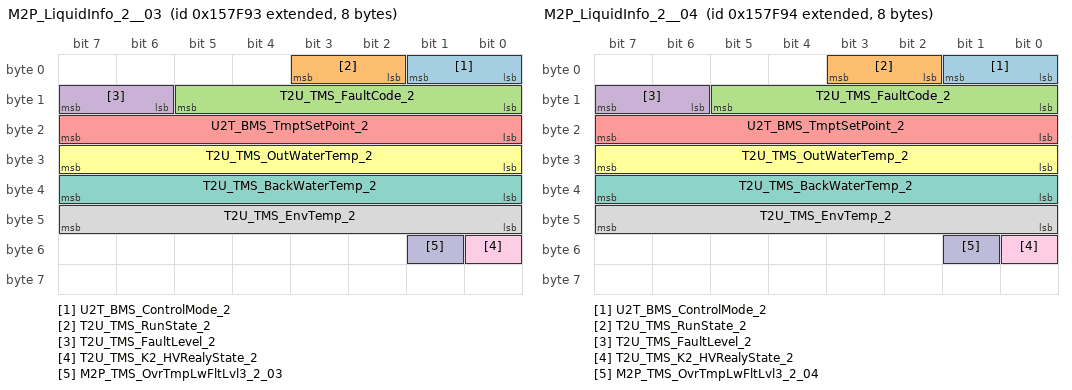
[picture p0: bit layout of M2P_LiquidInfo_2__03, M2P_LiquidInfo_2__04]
BO_ 2148892563 M2P_LiquidInfo_2__03: 8 MBMU
 SG_ U2T_BMS_ControlMode_2 : 0|2@1+ (1,0) [0|3] ""  PC
 SG_ T2U_TMS_RunState_2 : 2|2@1+ (1,0) [0|3] ""  PC
 SG_ T2U_TMS_FaultCode_2 : 8|6@1+ (1,0) [0|63] ""  PC
 SG_ T2U_TMS_FaultLevel_2 : 14|2@1+ (1,0) [0|3] ""  PC
 SG_ U2T_BMS_TmptSetPoint_2 : 16|8@1+ (1,-50) [-50|205] "℃"  PC
 SG_ T2U_TMS_OutWaterTemp_2 : 24|8@1+ (1,-50) [-50|205] "℃"  PC
 SG_ T2U_TMS_BackWaterTemp_2 : 32|8@1+ (1,-50) [-50|205] "℃"  PC
 SG_ T2U_TMS_EnvTemp_2 : 40|8@1+ (1,-50) [-50|205] "℃"  PC
 SG_ T2U_TMS_K2_HVRealyState_2 : 48|1@1+ (1,0) [0|1] ""  PC
 SG_ M2P_TMS_OvrTmpLwFltLvl3_2_03 : 49|1@1+ (1,0) [0|1] ""  PC

BO_ 2148892564 M2P_LiquidInfo_2__04: 8 MBMU
 SG_ U2T_BMS_ControlMode_2 : 0|2@1+ (1,0) [0|3] ""  PC
 SG_ T2U_TMS_RunState_2 : 2|2@1+ (1,0) [0|3] ""  PC
 SG_ T2U_TMS_FaultCode_2 : 8|6@1+ (1,0) [0|63] ""  PC
 SG_ T2U_TMS_FaultLevel_2 : 14|2@1+ (1,0) [0|3] ""  PC
 SG_ U2T_BMS_TmptSetPoint_2 : 16|8@1+ (1,-50) [-50|205] "℃"  PC
 SG_ T2U_TMS_OutWaterTemp_2 : 24|8@1+ (1,-50) [-50|205] "℃"  PC
 SG_ T2U_TMS_BackWaterTemp_2 : 32|8@1+ (1,-50) [-50|205] "℃"  PC
 SG_ T2U_TMS_EnvTemp_2 : 40|8@1+ (1,-50) [-50|205] "℃"  PC
 SG_ T2U_TMS_K2_HVRealyState_2 : 48|1@1+ (1,0) [0|1] ""  PC
 SG_ M2P_TMS_OvrTmpLwFltLvl3_2_04 : 49|1@1+ (1,0) [0|1] ""  PC

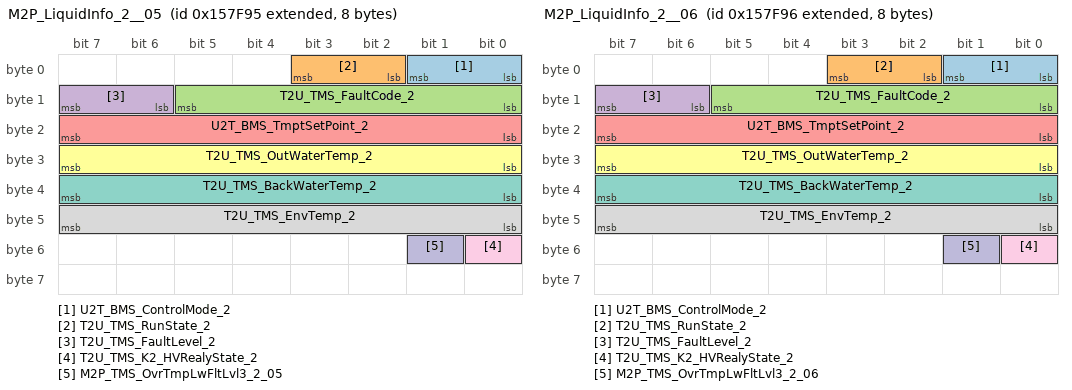
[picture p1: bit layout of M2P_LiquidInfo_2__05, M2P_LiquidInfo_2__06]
BO_ 2148892565 M2P_LiquidInfo_2__05: 8 MBMU
 SG_ U2T_BMS_ControlMode_2 : 0|2@1+ (1,0) [0|3] ""  PC
 SG_ T2U_TMS_RunState_2 : 2|2@1+ (1,0) [0|3] ""  PC
 SG_ T2U_TMS_FaultCode_2 : 8|6@1+ (1,0) [0|63] ""  PC
 SG_ T2U_TMS_FaultLevel_2 : 14|2@1+ (1,0) [0|3] ""  PC
 SG_ U2T_BMS_TmptSetPoint_2 : 16|8@1+ (1,-50) [-50|205] "℃"  PC
 SG_ T2U_TMS_OutWaterTemp_2 : 24|8@1+ (1,-50) [-50|205] "℃"  PC
 SG_ T2U_TMS_BackWaterTemp_2 : 32|8@1+ (1,-50) [-50|205] "℃"  PC
 SG_ T2U_TMS_EnvTemp_2 : 40|8@1+ (1,-50) [-50|205] "℃"  PC
 SG_ T2U_TMS_K2_HVRealyState_2 : 48|1@1+ (1,0) [0|1] ""  PC
 SG_ M2P_TMS_OvrTmpLwFltLvl3_2_05 : 49|1@1+ (1,0) [0|1] ""  PC

BO_ 2148892566 M2P_LiquidInfo_2__06: 8 MBMU
 SG_ U2T_BMS_ControlMode_2 : 0|2@1+ (1,0) [0|3] ""  PC
 SG_ T2U_TMS_RunState_2 : 2|2@1+ (1,0) [0|3] ""  PC
 SG_ T2U_TMS_FaultCode_2 : 8|6@1+ (1,0) [0|63] ""  PC
 SG_ T2U_TMS_FaultLevel_2 : 14|2@1+ (1,0) [0|3] ""  PC
 SG_ U2T_BMS_TmptSetPoint_2 : 16|8@1+ (1,-50) [-50|205] "℃"  PC
 SG_ T2U_TMS_OutWaterTemp_2 : 24|8@1+ (1,-50) [-50|205] "℃"  PC
 SG_ T2U_TMS_BackWaterTemp_2 : 32|8@1+ (1,-50) [-50|205] "℃"  PC
 SG_ T2U_TMS_EnvTemp_2 : 40|8@1+ (1,-50) [-50|205] "℃"  PC
 SG_ T2U_TMS_K2_HVRealyState_2 : 48|1@1+ (1,0) [0|1] ""  PC
 SG_ M2P_TMS_OvrTmpLwFltLvl3_2_06 : 49|1@1+ (1,0) [0|1] ""  PC

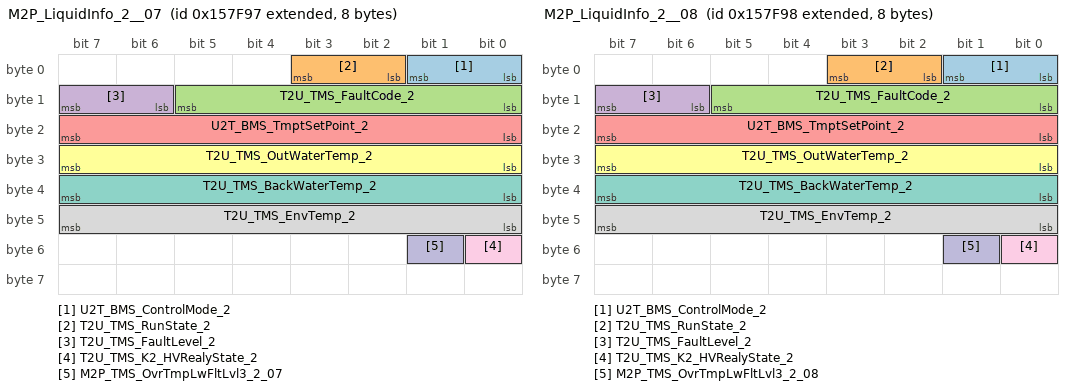
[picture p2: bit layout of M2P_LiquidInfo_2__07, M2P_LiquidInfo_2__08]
BO_ 2148892567 M2P_LiquidInfo_2__07: 8 MBMU
 SG_ U2T_BMS_ControlMode_2 : 0|2@1+ (1,0) [0|3] ""  PC
 SG_ T2U_TMS_RunState_2 : 2|2@1+ (1,0) [0|3] ""  PC
 SG_ T2U_TMS_FaultCode_2 : 8|6@1+ (1,0) [0|63] ""  PC
 SG_ T2U_TMS_FaultLevel_2 : 14|2@1+ (1,0) [0|3] ""  PC
 SG_ U2T_BMS_TmptSetPoint_2 : 16|8@1+ (1,-50) [-50|205] "℃"  PC
 SG_ T2U_TMS_OutWaterTemp_2 : 24|8@1+ (1,-50) [-50|205] "℃"  PC
 SG_ T2U_TMS_BackWaterTemp_2 : 32|8@1+ (1,-50) [-50|205] "℃"  PC
 SG_ T2U_TMS_EnvTemp_2 : 40|8@1+ (1,-50) [-50|205] "℃"  PC
 SG_ T2U_TMS_K2_HVRealyState_2 : 48|1@1+ (1,0) [0|1] ""  PC
 SG_ M2P_TMS_OvrTmpLwFltLvl3_2_07 : 49|1@1+ (1,0) [0|1] ""  PC

BO_ 2148892568 M2P_LiquidInfo_2__08: 8 MBMU
 SG_ U2T_BMS_ControlMode_2 : 0|2@1+ (1,0) [0|3] ""  PC
 SG_ T2U_TMS_RunState_2 : 2|2@1+ (1,0) [0|3] ""  PC
 SG_ T2U_TMS_FaultCode_2 : 8|6@1+ (1,0) [0|63] ""  PC
 SG_ T2U_TMS_FaultLevel_2 : 14|2@1+ (1,0) [0|3] ""  PC
 SG_ U2T_BMS_TmptSetPoint_2 : 16|8@1+ (1,-50) [-50|205] "℃"  PC
 SG_ T2U_TMS_OutWaterTemp_2 : 24|8@1+ (1,-50) [-50|205] "℃"  PC
 SG_ T2U_TMS_BackWaterTemp_2 : 32|8@1+ (1,-50) [-50|205] "℃"  PC
 SG_ T2U_TMS_EnvTemp_2 : 40|8@1+ (1,-50) [-50|205] "℃"  PC
 SG_ T2U_TMS_K2_HVRealyState_2 : 48|1@1+ (1,0) [0|1] ""  PC
 SG_ M2P_TMS_OvrTmpLwFltLvl3_2_08 : 49|1@1+ (1,0) [0|1] ""  PC

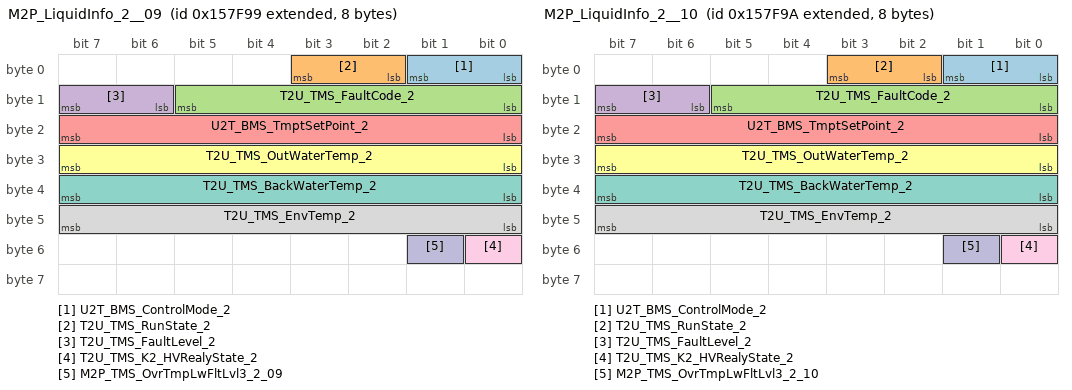
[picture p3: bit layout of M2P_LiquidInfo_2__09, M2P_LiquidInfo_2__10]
BO_ 2148892569 M2P_LiquidInfo_2__09: 8 MBMU
 SG_ U2T_BMS_ControlMode_2 : 0|2@1+ (1,0) [0|3] ""  PC
 SG_ T2U_TMS_RunState_2 : 2|2@1+ (1,0) [0|3] ""  PC
 SG_ T2U_TMS_FaultCode_2 : 8|6@1+ (1,0) [0|63] ""  PC
 SG_ T2U_TMS_FaultLevel_2 : 14|2@1+ (1,0) [0|3] ""  PC
 SG_ U2T_BMS_TmptSetPoint_2 : 16|8@1+ (1,-50) [-50|205] "℃"  PC
 SG_ T2U_TMS_OutWaterTemp_2 : 24|8@1+ (1,-50) [-50|205] "℃"  PC
 SG_ T2U_TMS_BackWaterTemp_2 : 32|8@1+ (1,-50) [-50|205] "℃"  PC
 SG_ T2U_TMS_EnvTemp_2 : 40|8@1+ (1,-50) [-50|205] "℃"  PC
 SG_ T2U_TMS_K2_HVRealyState_2 : 48|1@1+ (1,0) [0|1] ""  PC
 SG_ M2P_TMS_OvrTmpLwFltLvl3_2_09 : 49|1@1+ (1,0) [0|1] ""  PC

BO_ 2148892570 M2P_LiquidInfo_2__10: 8 MBMU
 SG_ U2T_BMS_ControlMode_2 : 0|2@1+ (1,0) [0|3] ""  PC
 SG_ T2U_TMS_RunState_2 : 2|2@1+ (1,0) [0|3] ""  PC
 SG_ T2U_TMS_FaultCode_2 : 8|6@1+ (1,0) [0|63] ""  PC
 SG_ T2U_TMS_FaultLevel_2 : 14|2@1+ (1,0) [0|3] ""  PC
 SG_ U2T_BMS_TmptSetPoint_2 : 16|8@1+ (1,-50) [-50|205] "℃"  PC
 SG_ T2U_TMS_OutWaterTemp_2 : 24|8@1+ (1,-50) [-50|205] "℃"  PC
 SG_ T2U_TMS_BackWaterTemp_2 : 32|8@1+ (1,-50) [-50|205] "℃"  PC
 SG_ T2U_TMS_EnvTemp_2 : 40|8@1+ (1,-50) [-50|205] "℃"  PC
 SG_ T2U_TMS_K2_HVRealyState_2 : 48|1@1+ (1,0) [0|1] ""  PC
 SG_ M2P_TMS_OvrTmpLwFltLvl3_2_10 : 49|1@1+ (1,0) [0|1] ""  PC

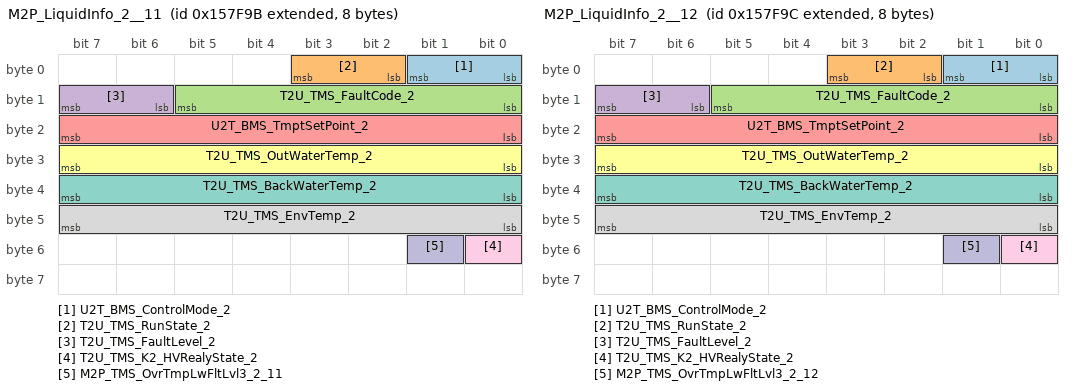
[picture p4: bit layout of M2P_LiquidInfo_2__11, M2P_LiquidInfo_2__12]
BO_ 2148892571 M2P_LiquidInfo_2__11: 8 MBMU
 SG_ U2T_BMS_ControlMode_2 : 0|2@1+ (1,0) [0|3] ""  PC
 SG_ T2U_TMS_RunState_2 : 2|2@1+ (1,0) [0|3] ""  PC
 SG_ T2U_TMS_FaultCode_2 : 8|6@1+ (1,0) [0|63] ""  PC
 SG_ T2U_TMS_FaultLevel_2 : 14|2@1+ (1,0) [0|3] ""  PC
 SG_ U2T_BMS_TmptSetPoint_2 : 16|8@1+ (1,-50) [-50|205] "℃"  PC
 SG_ T2U_TMS_OutWaterTemp_2 : 24|8@1+ (1,-50) [-50|205] "℃"  PC
 SG_ T2U_TMS_BackWaterTemp_2 : 32|8@1+ (1,-50) [-50|205] "℃"  PC
 SG_ T2U_TMS_EnvTemp_2 : 40|8@1+ (1,-50) [-50|205] "℃"  PC
 SG_ T2U_TMS_K2_HVRealyState_2 : 48|1@1+ (1,0) [0|1] ""  PC
 SG_ M2P_TMS_OvrTmpLwFltLvl3_2_11 : 49|1@1+ (1,0) [0|1] ""  PC

BO_ 2148892572 M2P_LiquidInfo_2__12: 8 MBMU
 SG_ U2T_BMS_ControlMode_2 : 0|2@1+ (1,0) [0|3] ""  PC
 SG_ T2U_TMS_RunState_2 : 2|2@1+ (1,0) [0|3] ""  PC
 SG_ T2U_TMS_FaultCode_2 : 8|6@1+ (1,0) [0|63] ""  PC
 SG_ T2U_TMS_FaultLevel_2 : 14|2@1+ (1,0) [0|3] ""  PC
 SG_ U2T_BMS_TmptSetPoint_2 : 16|8@1+ (1,-50) [-50|205] "℃"  PC
 SG_ T2U_TMS_OutWaterTemp_2 : 24|8@1+ (1,-50) [-50|205] "℃"  PC
 SG_ T2U_TMS_BackWaterTemp_2 : 32|8@1+ (1,-50) [-50|205] "℃"  PC
 SG_ T2U_TMS_EnvTemp_2 : 40|8@1+ (1,-50) [-50|205] "℃"  PC
 SG_ T2U_TMS_K2_HVRealyState_2 : 48|1@1+ (1,0) [0|1] ""  PC
 SG_ M2P_TMS_OvrTmpLwFltLvl3_2_12 : 49|1@1+ (1,0) [0|1] ""  PC

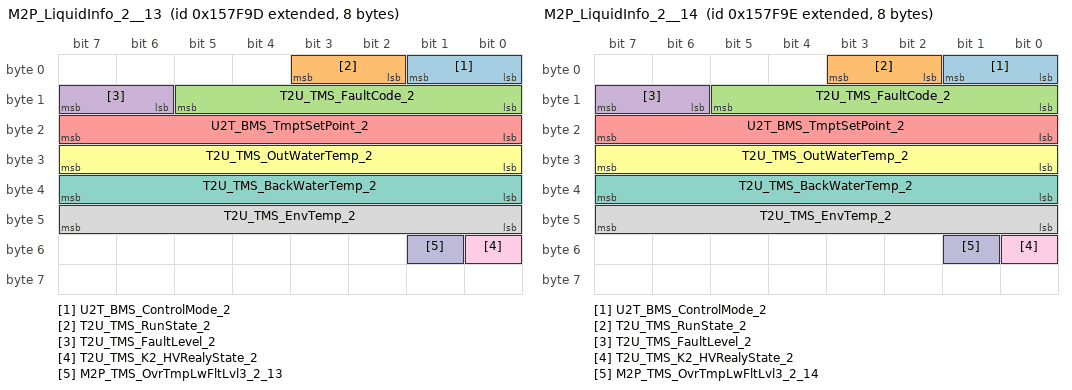
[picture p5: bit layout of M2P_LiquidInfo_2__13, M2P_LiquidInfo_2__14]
BO_ 2148892573 M2P_LiquidInfo_2__13: 8 MBMU
 SG_ U2T_BMS_ControlMode_2 : 0|2@1+ (1,0) [0|3] ""  PC
 SG_ T2U_TMS_RunState_2 : 2|2@1+ (1,0) [0|3] ""  PC
 SG_ T2U_TMS_FaultCode_2 : 8|6@1+ (1,0) [0|63] ""  PC
 SG_ T2U_TMS_FaultLevel_2 : 14|2@1+ (1,0) [0|3] ""  PC
 SG_ U2T_BMS_TmptSetPoint_2 : 16|8@1+ (1,-50) [-50|205] "℃"  PC
 SG_ T2U_TMS_OutWaterTemp_2 : 24|8@1+ (1,-50) [-50|205] "℃"  PC
 SG_ T2U_TMS_BackWaterTemp_2 : 32|8@1+ (1,-50) [-50|205] "℃"  PC
 SG_ T2U_TMS_EnvTemp_2 : 40|8@1+ (1,-50) [-50|205] "℃"  PC
 SG_ T2U_TMS_K2_HVRealyState_2 : 48|1@1+ (1,0) [0|1] ""  PC
 SG_ M2P_TMS_OvrTmpLwFltLvl3_2_13 : 49|1@1+ (1,0) [0|1] ""  PC

BO_ 2148892574 M2P_LiquidInfo_2__14: 8 MBMU
 SG_ U2T_BMS_ControlMode_2 : 0|2@1+ (1,0) [0|3] ""  PC
 SG_ T2U_TMS_RunState_2 : 2|2@1+ (1,0) [0|3] ""  PC
 SG_ T2U_TMS_FaultCode_2 : 8|6@1+ (1,0) [0|63] ""  PC
 SG_ T2U_TMS_FaultLevel_2 : 14|2@1+ (1,0) [0|3] ""  PC
 SG_ U2T_BMS_TmptSetPoint_2 : 16|8@1+ (1,-50) [-50|205] "℃"  PC
 SG_ T2U_TMS_OutWaterTemp_2 : 24|8@1+ (1,-50) [-50|205] "℃"  PC
 SG_ T2U_TMS_BackWaterTemp_2 : 32|8@1+ (1,-50) [-50|205] "℃"  PC
 SG_ T2U_TMS_EnvTemp_2 : 40|8@1+ (1,-50) [-50|205] "℃"  PC
 SG_ T2U_TMS_K2_HVRealyState_2 : 48|1@1+ (1,0) [0|1] ""  PC
 SG_ M2P_TMS_OvrTmpLwFltLvl3_2_14 : 49|1@1+ (1,0) [0|1] ""  PC

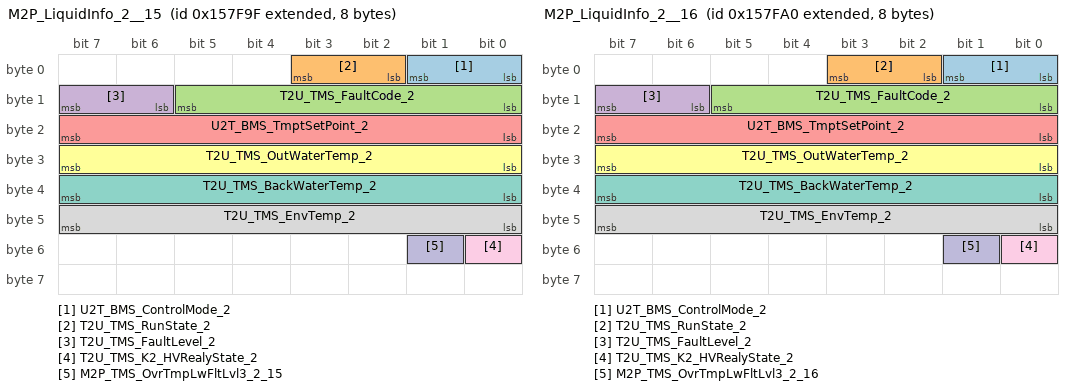
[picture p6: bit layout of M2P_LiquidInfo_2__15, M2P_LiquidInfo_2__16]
BO_ 2148892575 M2P_LiquidInfo_2__15: 8 MBMU
 SG_ U2T_BMS_ControlMode_2 : 0|2@1+ (1,0) [0|3] ""  PC
 SG_ T2U_TMS_RunState_2 : 2|2@1+ (1,0) [0|3] ""  PC
 SG_ T2U_TMS_FaultCode_2 : 8|6@1+ (1,0) [0|63] ""  PC
 SG_ T2U_TMS_FaultLevel_2 : 14|2@1+ (1,0) [0|3] ""  PC
 SG_ U2T_BMS_TmptSetPoint_2 : 16|8@1+ (1,-50) [-50|205] "℃"  PC
 SG_ T2U_TMS_OutWaterTemp_2 : 24|8@1+ (1,-50) [-50|205] "℃"  PC
 SG_ T2U_TMS_BackWaterTemp_2 : 32|8@1+ (1,-50) [-50|205] "℃"  PC
 SG_ T2U_TMS_EnvTemp_2 : 40|8@1+ (1,-50) [-50|205] "℃"  PC
 SG_ T2U_TMS_K2_HVRealyState_2 : 48|1@1+ (1,0) [0|1] ""  PC
 SG_ M2P_TMS_OvrTmpLwFltLvl3_2_15 : 49|1@1+ (1,0) [0|1] ""  PC

BO_ 2148892576 M2P_LiquidInfo_2__16: 8 MBMU
 SG_ U2T_BMS_ControlMode_2 : 0|2@1+ (1,0) [0|3] ""  PC
 SG_ T2U_TMS_RunState_2 : 2|2@1+ (1,0) [0|3] ""  PC
 SG_ T2U_TMS_FaultCode_2 : 8|6@1+ (1,0) [0|63] ""  PC
 SG_ T2U_TMS_FaultLevel_2 : 14|2@1+ (1,0) [0|3] ""  PC
 SG_ U2T_BMS_TmptSetPoint_2 : 16|8@1+ (1,-50) [-50|205] "℃"  PC
 SG_ T2U_TMS_OutWaterTemp_2 : 24|8@1+ (1,-50) [-50|205] "℃"  PC
 SG_ T2U_TMS_BackWaterTemp_2 : 32|8@1+ (1,-50) [-50|205] "℃"  PC
 SG_ T2U_TMS_EnvTemp_2 : 40|8@1+ (1,-50) [-50|205] "℃"  PC
 SG_ T2U_TMS_K2_HVRealyState_2 : 48|1@1+ (1,0) [0|1] ""  PC
 SG_ M2P_TMS_OvrTmpLwFltLvl3_2_16 : 49|1@1+ (1,0) [0|1] ""  PC

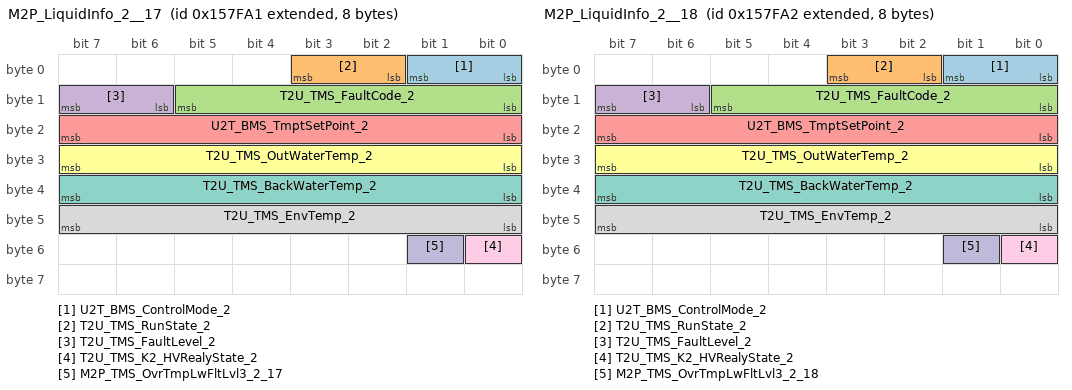
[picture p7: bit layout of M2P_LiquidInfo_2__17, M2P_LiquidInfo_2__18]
BO_ 2148892577 M2P_LiquidInfo_2__17: 8 MBMU
 SG_ U2T_BMS_ControlMode_2 : 0|2@1+ (1,0) [0|3] ""  PC
 SG_ T2U_TMS_RunState_2 : 2|2@1+ (1,0) [0|3] ""  PC
 SG_ T2U_TMS_FaultCode_2 : 8|6@1+ (1,0) [0|63] ""  PC
 SG_ T2U_TMS_FaultLevel_2 : 14|2@1+ (1,0) [0|3] ""  PC
 SG_ U2T_BMS_TmptSetPoint_2 : 16|8@1+ (1,-50) [-50|205] "℃"  PC
 SG_ T2U_TMS_OutWaterTemp_2 : 24|8@1+ (1,-50) [-50|205] "℃"  PC
 SG_ T2U_TMS_BackWaterTemp_2 : 32|8@1+ (1,-50) [-50|205] "℃"  PC
 SG_ T2U_TMS_EnvTemp_2 : 40|8@1+ (1,-50) [-50|205] "℃"  PC
 SG_ T2U_TMS_K2_HVRealyState_2 : 48|1@1+ (1,0) [0|1] ""  PC
 SG_ M2P_TMS_OvrTmpLwFltLvl3_2_17 : 49|1@1+ (1,0) [0|1] ""  PC

BO_ 2148892578 M2P_LiquidInfo_2__18: 8 MBMU
 SG_ U2T_BMS_ControlMode_2 : 0|2@1+ (1,0) [0|3] ""  PC
 SG_ T2U_TMS_RunState_2 : 2|2@1+ (1,0) [0|3] ""  PC
 SG_ T2U_TMS_FaultCode_2 : 8|6@1+ (1,0) [0|63] ""  PC
 SG_ T2U_TMS_FaultLevel_2 : 14|2@1+ (1,0) [0|3] ""  PC
 SG_ U2T_BMS_TmptSetPoint_2 : 16|8@1+ (1,-50) [-50|205] "℃"  PC
 SG_ T2U_TMS_OutWaterTemp_2 : 24|8@1+ (1,-50) [-50|205] "℃"  PC
 SG_ T2U_TMS_BackWaterTemp_2 : 32|8@1+ (1,-50) [-50|205] "℃"  PC
 SG_ T2U_TMS_EnvTemp_2 : 40|8@1+ (1,-50) [-50|205] "℃"  PC
 SG_ T2U_TMS_K2_HVRealyState_2 : 48|1@1+ (1,0) [0|1] ""  PC
 SG_ M2P_TMS_OvrTmpLwFltLvl3_2_18 : 49|1@1+ (1,0) [0|1] ""  PC

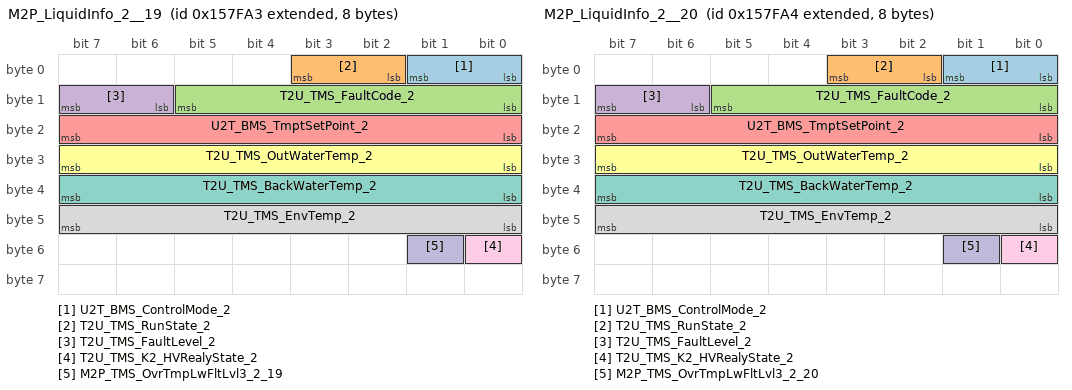
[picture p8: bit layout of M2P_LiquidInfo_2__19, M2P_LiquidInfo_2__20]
BO_ 2148892579 M2P_LiquidInfo_2__19: 8 MBMU
 SG_ U2T_BMS_ControlMode_2 : 0|2@1+ (1,0) [0|3] ""  PC
 SG_ T2U_TMS_RunState_2 : 2|2@1+ (1,0) [0|3] ""  PC
 SG_ T2U_TMS_FaultCode_2 : 8|6@1+ (1,0) [0|63] ""  PC
 SG_ T2U_TMS_FaultLevel_2 : 14|2@1+ (1,0) [0|3] ""  PC
 SG_ U2T_BMS_TmptSetPoint_2 : 16|8@1+ (1,-50) [-50|205] "℃"  PC
 SG_ T2U_TMS_OutWaterTemp_2 : 24|8@1+ (1,-50) [-50|205] "℃"  PC
 SG_ T2U_TMS_BackWaterTemp_2 : 32|8@1+ (1,-50) [-50|205] "℃"  PC
 SG_ T2U_TMS_EnvTemp_2 : 40|8@1+ (1,-50) [-50|205] "℃"  PC
 SG_ T2U_TMS_K2_HVRealyState_2 : 48|1@1+ (1,0) [0|1] ""  PC
 SG_ M2P_TMS_OvrTmpLwFltLvl3_2_19 : 49|1@1+ (1,0) [0|1] ""  PC

BO_ 2148892580 M2P_LiquidInfo_2__20: 8 MBMU
 SG_ U2T_BMS_ControlMode_2 : 0|2@1+ (1,0) [0|3] ""  PC
 SG_ T2U_TMS_RunState_2 : 2|2@1+ (1,0) [0|3] ""  PC
 SG_ T2U_TMS_FaultCode_2 : 8|6@1+ (1,0) [0|63] ""  PC
 SG_ T2U_TMS_FaultLevel_2 : 14|2@1+ (1,0) [0|3] ""  PC
 SG_ U2T_BMS_TmptSetPoint_2 : 16|8@1+ (1,-50) [-50|205] "℃"  PC
 SG_ T2U_TMS_OutWaterTemp_2 : 24|8@1+ (1,-50) [-50|205] "℃"  PC
 SG_ T2U_TMS_BackWaterTemp_2 : 32|8@1+ (1,-50) [-50|205] "℃"  PC
 SG_ T2U_TMS_EnvTemp_2 : 40|8@1+ (1,-50) [-50|205] "℃"  PC
 SG_ T2U_TMS_K2_HVRealyState_2 : 48|1@1+ (1,0) [0|1] ""  PC
 SG_ M2P_TMS_OvrTmpLwFltLvl3_2_20 : 49|1@1+ (1,0) [0|1] ""  PC

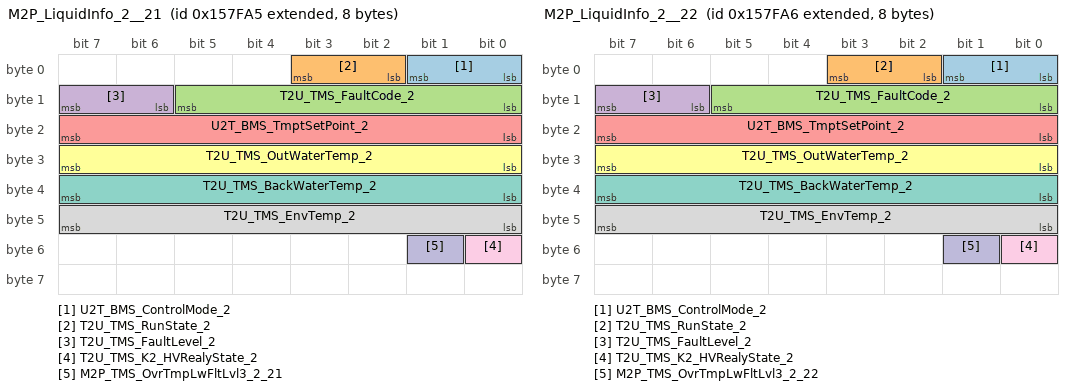
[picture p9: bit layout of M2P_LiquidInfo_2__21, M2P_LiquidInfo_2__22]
BO_ 2148892581 M2P_LiquidInfo_2__21: 8 MBMU
 SG_ U2T_BMS_ControlMode_2 : 0|2@1+ (1,0) [0|3] ""  PC
 SG_ T2U_TMS_RunState_2 : 2|2@1+ (1,0) [0|3] ""  PC
 SG_ T2U_TMS_FaultCode_2 : 8|6@1+ (1,0) [0|63] ""  PC
 SG_ T2U_TMS_FaultLevel_2 : 14|2@1+ (1,0) [0|3] ""  PC
 SG_ U2T_BMS_TmptSetPoint_2 : 16|8@1+ (1,-50) [-50|205] "℃"  PC
 SG_ T2U_TMS_OutWaterTemp_2 : 24|8@1+ (1,-50) [-50|205] "℃"  PC
 SG_ T2U_TMS_BackWaterTemp_2 : 32|8@1+ (1,-50) [-50|205] "℃"  PC
 SG_ T2U_TMS_EnvTemp_2 : 40|8@1+ (1,-50) [-50|205] "℃"  PC
 SG_ T2U_TMS_K2_HVRealyState_2 : 48|1@1+ (1,0) [0|1] ""  PC
 SG_ M2P_TMS_OvrTmpLwFltLvl3_2_21 : 49|1@1+ (1,0) [0|1] ""  PC

BO_ 2148892582 M2P_LiquidInfo_2__22: 8 MBMU
 SG_ U2T_BMS_ControlMode_2 : 0|2@1+ (1,0) [0|3] ""  PC
 SG_ T2U_TMS_RunState_2 : 2|2@1+ (1,0) [0|3] ""  PC
 SG_ T2U_TMS_FaultCode_2 : 8|6@1+ (1,0) [0|63] ""  PC
 SG_ T2U_TMS_FaultLevel_2 : 14|2@1+ (1,0) [0|3] ""  PC
 SG_ U2T_BMS_TmptSetPoint_2 : 16|8@1+ (1,-50) [-50|205] "℃"  PC
 SG_ T2U_TMS_OutWaterTemp_2 : 24|8@1+ (1,-50) [-50|205] "℃"  PC
 SG_ T2U_TMS_BackWaterTemp_2 : 32|8@1+ (1,-50) [-50|205] "℃"  PC
 SG_ T2U_TMS_EnvTemp_2 : 40|8@1+ (1,-50) [-50|205] "℃"  PC
 SG_ T2U_TMS_K2_HVRealyState_2 : 48|1@1+ (1,0) [0|1] ""  PC
 SG_ M2P_TMS_OvrTmpLwFltLvl3_2_22 : 49|1@1+ (1,0) [0|1] ""  PC

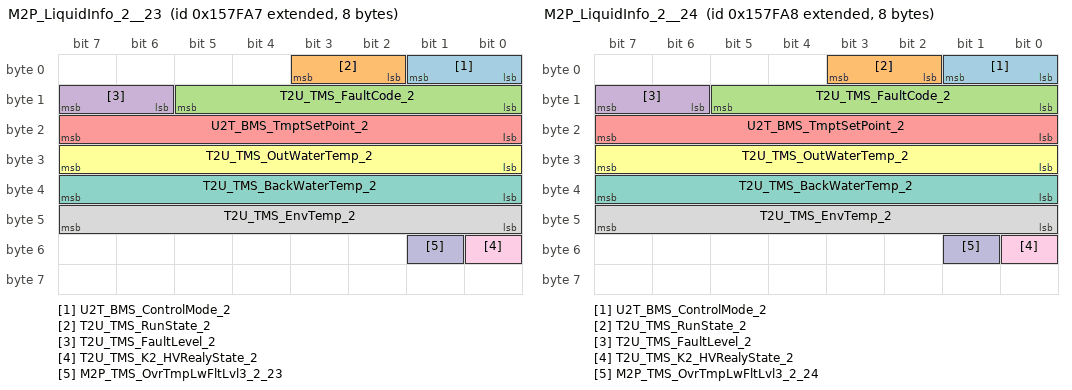
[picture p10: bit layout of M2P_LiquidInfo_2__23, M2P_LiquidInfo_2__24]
BO_ 2148892583 M2P_LiquidInfo_2__23: 8 MBMU
 SG_ U2T_BMS_ControlMode_2 : 0|2@1+ (1,0) [0|3] ""  PC
 SG_ T2U_TMS_RunState_2 : 2|2@1+ (1,0) [0|3] ""  PC
 SG_ T2U_TMS_FaultCode_2 : 8|6@1+ (1,0) [0|63] ""  PC
 SG_ T2U_TMS_FaultLevel_2 : 14|2@1+ (1,0) [0|3] ""  PC
 SG_ U2T_BMS_TmptSetPoint_2 : 16|8@1+ (1,-50) [-50|205] "℃"  PC
 SG_ T2U_TMS_OutWaterTemp_2 : 24|8@1+ (1,-50) [-50|205] "℃"  PC
 SG_ T2U_TMS_BackWaterTemp_2 : 32|8@1+ (1,-50) [-50|205] "℃"  PC
 SG_ T2U_TMS_EnvTemp_2 : 40|8@1+ (1,-50) [-50|205] "℃"  PC
 SG_ T2U_TMS_K2_HVRealyState_2 : 48|1@1+ (1,0) [0|1] ""  PC
 SG_ M2P_TMS_OvrTmpLwFltLvl3_2_23 : 49|1@1+ (1,0) [0|1] ""  PC

BO_ 2148892584 M2P_LiquidInfo_2__24: 8 MBMU
 SG_ U2T_BMS_ControlMode_2 : 0|2@1+ (1,0) [0|3] ""  PC
 SG_ T2U_TMS_RunState_2 : 2|2@1+ (1,0) [0|3] ""  PC
 SG_ T2U_TMS_FaultCode_2 : 8|6@1+ (1,0) [0|63] ""  PC
 SG_ T2U_TMS_FaultLevel_2 : 14|2@1+ (1,0) [0|3] ""  PC
 SG_ U2T_BMS_TmptSetPoint_2 : 16|8@1+ (1,-50) [-50|205] "℃"  PC
 SG_ T2U_TMS_OutWaterTemp_2 : 24|8@1+ (1,-50) [-50|205] "℃"  PC
 SG_ T2U_TMS_BackWaterTemp_2 : 32|8@1+ (1,-50) [-50|205] "℃"  PC
 SG_ T2U_TMS_EnvTemp_2 : 40|8@1+ (1,-50) [-50|205] "℃"  PC
 SG_ T2U_TMS_K2_HVRealyState_2 : 48|1@1+ (1,0) [0|1] ""  PC
 SG_ M2P_TMS_OvrTmpLwFltLvl3_2_24 : 49|1@1+ (1,0) [0|1] ""  PC

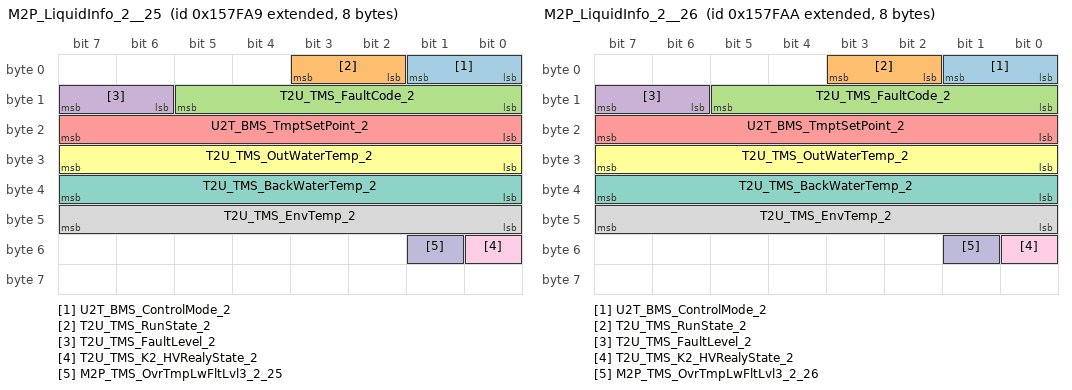
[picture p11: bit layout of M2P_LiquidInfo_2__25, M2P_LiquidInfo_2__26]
BO_ 2148892585 M2P_LiquidInfo_2__25: 8 MBMU
 SG_ U2T_BMS_ControlMode_2 : 0|2@1+ (1,0) [0|3] ""  PC
 SG_ T2U_TMS_RunState_2 : 2|2@1+ (1,0) [0|3] ""  PC
 SG_ T2U_TMS_FaultCode_2 : 8|6@1+ (1,0) [0|63] ""  PC
 SG_ T2U_TMS_FaultLevel_2 : 14|2@1+ (1,0) [0|3] ""  PC
 SG_ U2T_BMS_TmptSetPoint_2 : 16|8@1+ (1,-50) [-50|205] "℃"  PC
 SG_ T2U_TMS_OutWaterTemp_2 : 24|8@1+ (1,-50) [-50|205] "℃"  PC
 SG_ T2U_TMS_BackWaterTemp_2 : 32|8@1+ (1,-50) [-50|205] "℃"  PC
 SG_ T2U_TMS_EnvTemp_2 : 40|8@1+ (1,-50) [-50|205] "℃"  PC
 SG_ T2U_TMS_K2_HVRealyState_2 : 48|1@1+ (1,0) [0|1] ""  PC
 SG_ M2P_TMS_OvrTmpLwFltLvl3_2_25 : 49|1@1+ (1,0) [0|1] ""  PC

BO_ 2148892586 M2P_LiquidInfo_2__26: 8 MBMU
 SG_ U2T_BMS_ControlMode_2 : 0|2@1+ (1,0) [0|3] ""  PC
 SG_ T2U_TMS_RunState_2 : 2|2@1+ (1,0) [0|3] ""  PC
 SG_ T2U_TMS_FaultCode_2 : 8|6@1+ (1,0) [0|63] ""  PC
 SG_ T2U_TMS_FaultLevel_2 : 14|2@1+ (1,0) [0|3] ""  PC
 SG_ U2T_BMS_TmptSetPoint_2 : 16|8@1+ (1,-50) [-50|205] "℃"  PC
 SG_ T2U_TMS_OutWaterTemp_2 : 24|8@1+ (1,-50) [-50|205] "℃"  PC
 SG_ T2U_TMS_BackWaterTemp_2 : 32|8@1+ (1,-50) [-50|205] "℃"  PC
 SG_ T2U_TMS_EnvTemp_2 : 40|8@1+ (1,-50) [-50|205] "℃"  PC
 SG_ T2U_TMS_K2_HVRealyState_2 : 48|1@1+ (1,0) [0|1] ""  PC
 SG_ M2P_TMS_OvrTmpLwFltLvl3_2_26 : 49|1@1+ (1,0) [0|1] ""  PC

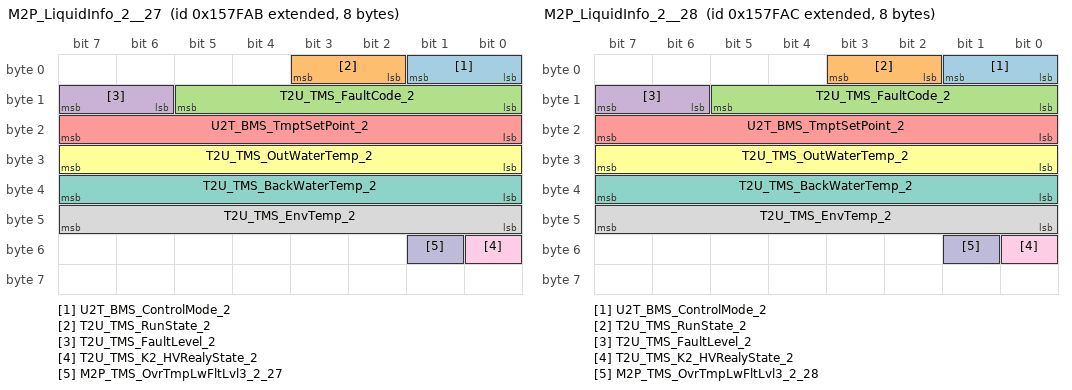
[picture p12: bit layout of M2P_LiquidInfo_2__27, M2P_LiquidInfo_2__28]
BO_ 2148892587 M2P_LiquidInfo_2__27: 8 MBMU
 SG_ U2T_BMS_ControlMode_2 : 0|2@1+ (1,0) [0|3] ""  PC
 SG_ T2U_TMS_RunState_2 : 2|2@1+ (1,0) [0|3] ""  PC
 SG_ T2U_TMS_FaultCode_2 : 8|6@1+ (1,0) [0|63] ""  PC
 SG_ T2U_TMS_FaultLevel_2 : 14|2@1+ (1,0) [0|3] ""  PC
 SG_ U2T_BMS_TmptSetPoint_2 : 16|8@1+ (1,-50) [-50|205] "℃"  PC
 SG_ T2U_TMS_OutWaterTemp_2 : 24|8@1+ (1,-50) [-50|205] "℃"  PC
 SG_ T2U_TMS_BackWaterTemp_2 : 32|8@1+ (1,-50) [-50|205] "℃"  PC
 SG_ T2U_TMS_EnvTemp_2 : 40|8@1+ (1,-50) [-50|205] "℃"  PC
 SG_ T2U_TMS_K2_HVRealyState_2 : 48|1@1+ (1,0) [0|1] ""  PC
 SG_ M2P_TMS_OvrTmpLwFltLvl3_2_27 : 49|1@1+ (1,0) [0|1] ""  PC

BO_ 2148892588 M2P_LiquidInfo_2__28: 8 MBMU
 SG_ U2T_BMS_ControlMode_2 : 0|2@1+ (1,0) [0|3] ""  PC
 SG_ T2U_TMS_RunState_2 : 2|2@1+ (1,0) [0|3] ""  PC
 SG_ T2U_TMS_FaultCode_2 : 8|6@1+ (1,0) [0|63] ""  PC
 SG_ T2U_TMS_FaultLevel_2 : 14|2@1+ (1,0) [0|3] ""  PC
 SG_ U2T_BMS_TmptSetPoint_2 : 16|8@1+ (1,-50) [-50|205] "℃"  PC
 SG_ T2U_TMS_OutWaterTemp_2 : 24|8@1+ (1,-50) [-50|205] "℃"  PC
 SG_ T2U_TMS_BackWaterTemp_2 : 32|8@1+ (1,-50) [-50|205] "℃"  PC
 SG_ T2U_TMS_EnvTemp_2 : 40|8@1+ (1,-50) [-50|205] "℃"  PC
 SG_ T2U_TMS_K2_HVRealyState_2 : 48|1@1+ (1,0) [0|1] ""  PC
 SG_ M2P_TMS_OvrTmpLwFltLvl3_2_28 : 49|1@1+ (1,0) [0|1] ""  PC

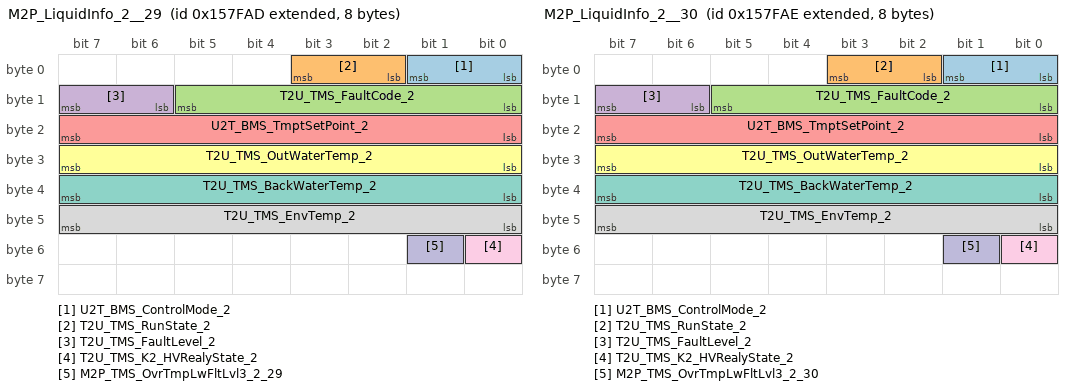
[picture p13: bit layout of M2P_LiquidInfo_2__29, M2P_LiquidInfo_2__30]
BO_ 2148892589 M2P_LiquidInfo_2__29: 8 MBMU
 SG_ U2T_BMS_ControlMode_2 : 0|2@1+ (1,0) [0|3] ""  PC
 SG_ T2U_TMS_RunState_2 : 2|2@1+ (1,0) [0|3] ""  PC
 SG_ T2U_TMS_FaultCode_2 : 8|6@1+ (1,0) [0|63] ""  PC
 SG_ T2U_TMS_FaultLevel_2 : 14|2@1+ (1,0) [0|3] ""  PC
 SG_ U2T_BMS_TmptSetPoint_2 : 16|8@1+ (1,-50) [-50|205] "℃"  PC
 SG_ T2U_TMS_OutWaterTemp_2 : 24|8@1+ (1,-50) [-50|205] "℃"  PC
 SG_ T2U_TMS_BackWaterTemp_2 : 32|8@1+ (1,-50) [-50|205] "℃"  PC
 SG_ T2U_TMS_EnvTemp_2 : 40|8@1+ (1,-50) [-50|205] "℃"  PC
 SG_ T2U_TMS_K2_HVRealyState_2 : 48|1@1+ (1,0) [0|1] ""  PC
 SG_ M2P_TMS_OvrTmpLwFltLvl3_2_29 : 49|1@1+ (1,0) [0|1] ""  PC

BO_ 2148892590 M2P_LiquidInfo_2__30: 8 MBMU
 SG_ U2T_BMS_ControlMode_2 : 0|2@1+ (1,0) [0|3] ""  PC
 SG_ T2U_TMS_RunState_2 : 2|2@1+ (1,0) [0|3] ""  PC
 SG_ T2U_TMS_FaultCode_2 : 8|6@1+ (1,0) [0|63] ""  PC
 SG_ T2U_TMS_FaultLevel_2 : 14|2@1+ (1,0) [0|3] ""  PC
 SG_ U2T_BMS_TmptSetPoint_2 : 16|8@1+ (1,-50) [-50|205] "℃"  PC
 SG_ T2U_TMS_OutWaterTemp_2 : 24|8@1+ (1,-50) [-50|205] "℃"  PC
 SG_ T2U_TMS_BackWaterTemp_2 : 32|8@1+ (1,-50) [-50|205] "℃"  PC
 SG_ T2U_TMS_EnvTemp_2 : 40|8@1+ (1,-50) [-50|205] "℃"  PC
 SG_ T2U_TMS_K2_HVRealyState_2 : 48|1@1+ (1,0) [0|1] ""  PC
 SG_ M2P_TMS_OvrTmpLwFltLvl3_2_30 : 49|1@1+ (1,0) [0|1] ""  PC

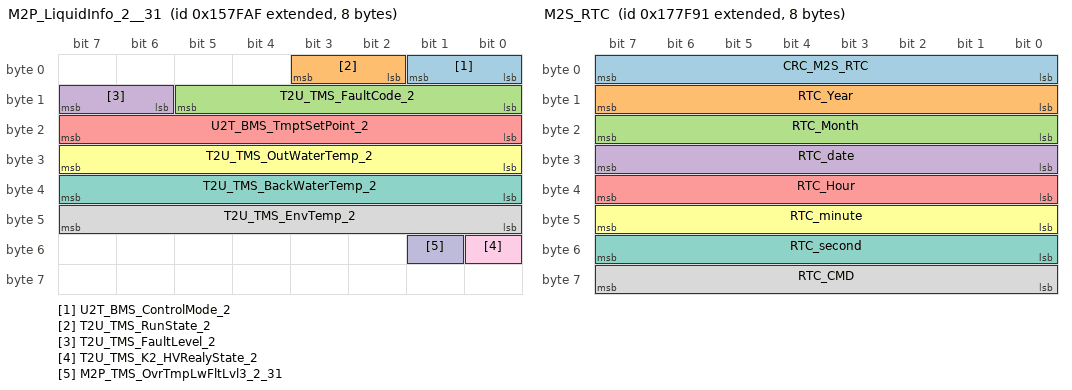
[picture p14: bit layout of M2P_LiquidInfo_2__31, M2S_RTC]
BO_ 2148892591 M2P_LiquidInfo_2__31: 8 MBMU
 SG_ U2T_BMS_ControlMode_2 : 0|2@1+ (1,0) [0|3] ""  PC
 SG_ T2U_TMS_RunState_2 : 2|2@1+ (1,0) [0|3] ""  PC
 SG_ T2U_TMS_FaultCode_2 : 8|6@1+ (1,0) [0|63] ""  PC
 SG_ T2U_TMS_FaultLevel_2 : 14|2@1+ (1,0) [0|3] ""  PC
 SG_ U2T_BMS_TmptSetPoint_2 : 16|8@1+ (1,-50) [-50|205] "℃"  PC
 SG_ T2U_TMS_OutWaterTemp_2 : 24|8@1+ (1,-50) [-50|205] "℃"  PC
 SG_ T2U_TMS_BackWaterTemp_2 : 32|8@1+ (1,-50) [-50|205] "℃"  PC
 SG_ T2U_TMS_EnvTemp_2 : 40|8@1+ (1,-50) [-50|205] "℃"  PC
 SG_ T2U_TMS_K2_HVRealyState_2 : 48|1@1+ (1,0) [0|1] ""  PC
 SG_ M2P_TMS_OvrTmpLwFltLvl3_2_31 : 49|1@1+ (1,0) [0|1] ""  PC

BO_ 2349461137 M2M_SUMDATA1: 8 MBMU
 SG_ IsoFault : 0|1@1+ (1,0) [0|1] ""  MBMU
 SG_ M2M_SUMDATA1_Reserved : 1|63@1+ (1,0) [0|9.22337203685478E+018] ""  MBMU

BO_ 2149023633 M2S_RTC: 8 MBMU
 SG_ CRC_M2S_RTC : 0|8@1+ (1,0) [0|255] ""  SBMU
 SG_ RTC_Year : 8|8@1+ (1,2000) [0|2255] ""  SBMU
 SG_ RTC_Month : 16|8@1+ (1,0) [0|255] ""  SBMU
 SG_ RTC_date : 24|8@1+ (1,0) [0|255] ""  SBMU
 SG_ RTC_Hour : 32|8@1+ (1,0) [0|255] ""  SBMU
 SG_ RTC_minute : 40|8@1+ (1,0) [0|255] ""  SBMU
 SG_ RTC_second : 48|8@1+ (1,0) [0|255] ""  SBMU
 SG_ RTC_CMD : 56|8@1+ (1,0) [0|255] ""  SBMU

BO_ 2149023634 M2S_RTC: 8 MBMU
 SG_ CRC_M2S_RTC : 0|8@1+ (1,0) [0|255] ""  SBMU
 SG_ RTC_Year : 8|8@1+ (1,2000) [0|2255] ""  SBMU
 SG_ RTC_Month : 16|8@1+ (1,0) [0|255] ""  SBMU
 SG_ RTC_date : 24|8@1+ (1,0) [0|255] ""  SBMU
 SG_ RTC_Hour : 32|8@1+ (1,0) [0|255] ""  SBMU
 SG_ RTC_minute : 40|8@1+ (1,0) [0|255] ""  SBMU
 SG_ RTC_second : 48|8@1+ (1,0) [0|255] ""  SBMU
 SG_ RTC_CMD : 56|8@1+ (1,0) [0|255] ""  SBMU

BO_ 2149023635 M2S_RTC: 8 MBMU
 SG_ CRC_M2S_RTC : 0|8@1+ (1,0) [0|255] ""  SBMU
 SG_ RTC_Year : 8|8@1+ (1,2000) [0|2255] ""  SBMU
 SG_ RTC_Month : 16|8@1+ (1,0) [0|255] ""  SBMU
 SG_ RTC_date : 24|8@1+ (1,0) [0|255] ""  SBMU
 SG_ RTC_Hour : 32|8@1+ (1,0) [0|255] ""  SBMU
 SG_ RTC_minute : 40|8@1+ (1,0) [0|255] ""  SBMU
 SG_ RTC_second : 48|8@1+ (1,0) [0|255] ""  SBMU
 SG_ RTC_CMD : 56|8@1+ (1,0) [0|255] ""  SBMU

BO_ 2149023636 M2S_RTC: 8 MBMU
 SG_ CRC_M2S_RTC : 0|8@1+ (1,0) [0|255] ""  SBMU
 SG_ RTC_Year : 8|8@1+ (1,2000) [0|2255] ""  SBMU
 SG_ RTC_Month : 16|8@1+ (1,0) [0|255] ""  SBMU
 SG_ RTC_date : 24|8@1+ (1,0) [0|255] ""  SBMU
 SG_ RTC_Hour : 32|8@1+ (1,0) [0|255] ""  SBMU
 SG_ RTC_minute : 40|8@1+ (1,0) [0|255] ""  SBMU
 SG_ RTC_second : 48|8@1+ (1,0) [0|255] ""  SBMU
 SG_ RTC_CMD : 56|8@1+ (1,0) [0|255] ""  SBMU

BO_ 2149023637 M2S_RTC: 8 MBMU
 SG_ CRC_M2S_RTC : 0|8@1+ (1,0) [0|255] ""  SBMU
 SG_ RTC_Year : 8|8@1+ (1,2000) [0|2255] ""  SBMU
 SG_ RTC_Month : 16|8@1+ (1,0) [0|255] ""  SBMU
 SG_ RTC_date : 24|8@1+ (1,0) [0|255] ""  SBMU
 SG_ RTC_Hour : 32|8@1+ (1,0) [0|255] ""  SBMU
 SG_ RTC_minute : 40|8@1+ (1,0) [0|255] ""  SBMU
 SG_ RTC_second : 48|8@1+ (1,0) [0|255] ""  SBMU
 SG_ RTC_CMD : 56|8@1+ (1,0) [0|255] ""  SBMU

BO_ 2149023638 M2S_RTC: 8 MBMU
 SG_ CRC_M2S_RTC : 0|8@1+ (1,0) [0|255] ""  SBMU
 SG_ RTC_Year : 8|8@1+ (1,2000) [0|2255] ""  SBMU
 SG_ RTC_Month : 16|8@1+ (1,0) [0|255] ""  SBMU
 SG_ RTC_date : 24|8@1+ (1,0) [0|255] ""  SBMU
 SG_ RTC_Hour : 32|8@1+ (1,0) [0|255] ""  SBMU
 SG_ RTC_minute : 40|8@1+ (1,0) [0|255] ""  SBMU
 SG_ RTC_second : 48|8@1+ (1,0) [0|255] ""  SBMU
 SG_ RTC_CMD : 56|8@1+ (1,0) [0|255] ""  SBMU

BO_ 2149023639 M2S_RTC: 8 MBMU
 SG_ CRC_M2S_RTC : 0|8@1+ (1,0) [0|255] ""  SBMU
 SG_ RTC_Year : 8|8@1+ (1,2000) [0|2255] ""  SBMU
 SG_ RTC_Month : 16|8@1+ (1,0) [0|255] ""  SBMU
 SG_ RTC_date : 24|8@1+ (1,0) [0|255] ""  SBMU
 SG_ RTC_Hour : 32|8@1+ (1,0) [0|255] ""  SBMU
 SG_ RTC_minute : 40|8@1+ (1,0) [0|255] ""  SBMU
 SG_ RTC_second : 48|8@1+ (1,0) [0|255] ""  SBMU
 SG_ RTC_CMD : 56|8@1+ (1,0) [0|255] ""  SBMU

BO_ 2149023640 M2S_RTC: 8 MBMU
 SG_ CRC_M2S_RTC : 0|8@1+ (1,0) [0|255] ""  SBMU
 SG_ RTC_Year : 8|8@1+ (1,2000) [0|2255] ""  SBMU
 SG_ RTC_Month : 16|8@1+ (1,0) [0|255] ""  SBMU
 SG_ RTC_date : 24|8@1+ (1,0) [0|255] ""  SBMU
 SG_ RTC_Hour : 32|8@1+ (1,0) [0|255] ""  SBMU
 SG_ RTC_minute : 40|8@1+ (1,0) [0|255] ""  SBMU
 SG_ RTC_second : 48|8@1+ (1,0) [0|255] ""  SBMU
 SG_ RTC_CMD : 56|8@1+ (1,0) [0|255] ""  SBMU

BO_ 2149023641 M2S_RTC: 8 MBMU
 SG_ CRC_M2S_RTC : 0|8@1+ (1,0) [0|255] ""  SBMU
 SG_ RTC_Year : 8|8@1+ (1,2000) [0|2255] ""  SBMU
 SG_ RTC_Month : 16|8@1+ (1,0) [0|255] ""  SBMU
 SG_ RTC_date : 24|8@1+ (1,0) [0|255] ""  SBMU
 SG_ RTC_Hour : 32|8@1+ (1,0) [0|255] ""  SBMU
 SG_ RTC_minute : 40|8@1+ (1,0) [0|255] ""  SBMU
 SG_ RTC_second : 48|8@1+ (1,0) [0|255] ""  SBMU
 SG_ RTC_CMD : 56|8@1+ (1,0) [0|255] ""  SBMU

BO_ 2149023642 M2S_RTC: 8 MBMU
 SG_ CRC_M2S_RTC : 0|8@1+ (1,0) [0|255] ""  SBMU
 SG_ RTC_Year : 8|8@1+ (1,2000) [0|2255] ""  SBMU
 SG_ RTC_Month : 16|8@1+ (1,0) [0|255] ""  SBMU
 SG_ RTC_date : 24|8@1+ (1,0) [0|255] ""  SBMU
 SG_ RTC_Hour : 32|8@1+ (1,0) [0|255] ""  SBMU
 SG_ RTC_minute : 40|8@1+ (1,0) [0|255] ""  SBMU
 SG_ RTC_second : 48|8@1+ (1,0) [0|255] ""  SBMU
 SG_ RTC_CMD : 56|8@1+ (1,0) [0|255] ""  SBMU

BO_ 2149023643 M2S_RTC: 8 MBMU
 SG_ CRC_M2S_RTC : 0|8@1+ (1,0) [0|255] ""  SBMU
 SG_ RTC_Year : 8|8@1+ (1,2000) [0|2255] ""  SBMU
 SG_ RTC_Month : 16|8@1+ (1,0) [0|255] ""  SBMU
 SG_ RTC_date : 24|8@1+ (1,0) [0|255] ""  SBMU
 SG_ RTC_Hour : 32|8@1+ (1,0) [0|255] ""  SBMU
 SG_ RTC_minute : 40|8@1+ (1,0) [0|255] ""  SBMU
 SG_ RTC_second : 48|8@1+ (1,0) [0|255] ""  SBMU
 SG_ RTC_CMD : 56|8@1+ (1,0) [0|255] ""  SBMU

BO_ 2149023644 M2S_RTC: 8 MBMU
 SG_ CRC_M2S_RTC : 0|8@1+ (1,0) [0|255] ""  SBMU
 SG_ RTC_Year : 8|8@1+ (1,2000) [0|2255] ""  SBMU
 SG_ RTC_Month : 16|8@1+ (1,0) [0|255] ""  SBMU
 SG_ RTC_date : 24|8@1+ (1,0) [0|255] ""  SBMU
 SG_ RTC_Hour : 32|8@1+ (1,0) [0|255] ""  SBMU
 SG_ RTC_minute : 40|8@1+ (1,0) [0|255] ""  SBMU
 SG_ RTC_second : 48|8@1+ (1,0) [0|255] ""  SBMU
 SG_ RTC_CMD : 56|8@1+ (1,0) [0|255] ""  SBMU

BO_ 2149023645 M2S_RTC: 8 MBMU
 SG_ CRC_M2S_RTC : 0|8@1+ (1,0) [0|255] ""  SBMU
 SG_ RTC_Year : 8|8@1+ (1,2000) [0|2255] ""  SBMU
 SG_ RTC_Month : 16|8@1+ (1,0) [0|255] ""  SBMU
 SG_ RTC_date : 24|8@1+ (1,0) [0|255] ""  SBMU
 SG_ RTC_Hour : 32|8@1+ (1,0) [0|255] ""  SBMU
 SG_ RTC_minute : 40|8@1+ (1,0) [0|255] ""  SBMU
 SG_ RTC_second : 48|8@1+ (1,0) [0|255] ""  SBMU
 SG_ RTC_CMD : 56|8@1+ (1,0) [0|255] ""  SBMU

BO_ 2149023646 M2S_RTC: 8 MBMU
 SG_ CRC_M2S_RTC : 0|8@1+ (1,0) [0|255] ""  SBMU
 SG_ RTC_Year : 8|8@1+ (1,2000) [0|2255] ""  SBMU
 SG_ RTC_Month : 16|8@1+ (1,0) [0|255] ""  SBMU
 SG_ RTC_date : 24|8@1+ (1,0) [0|255] ""  SBMU
 SG_ RTC_Hour : 32|8@1+ (1,0) [0|255] ""  SBMU
 SG_ RTC_minute : 40|8@1+ (1,0) [0|255] ""  SBMU
 SG_ RTC_second : 48|8@1+ (1,0) [0|255] ""  SBMU
 SG_ RTC_CMD : 56|8@1+ (1,0) [0|255] ""  SBMU

BO_ 2149023647 M2S_RTC: 8 MBMU
 SG_ CRC_M2S_RTC : 0|8@1+ (1,0) [0|255] ""  SBMU
 SG_ RTC_Year : 8|8@1+ (1,2000) [0|2255] ""  SBMU
 SG_ RTC_Month : 16|8@1+ (1,0) [0|255] ""  SBMU
 SG_ RTC_date : 24|8@1+ (1,0) [0|255] ""  SBMU
 SG_ RTC_Hour : 32|8@1+ (1,0) [0|255] ""  SBMU
 SG_ RTC_minute : 40|8@1+ (1,0) [0|255] ""  SBMU
 SG_ RTC_second : 48|8@1+ (1,0) [0|255] ""  SBMU
 SG_ RTC_CMD : 56|8@1+ (1,0) [0|255] ""  SBMU

BO_ 2149023648 M2S_RTC: 8 MBMU
 SG_ CRC_M2S_RTC : 0|8@1+ (1,0) [0|255] ""  SBMU
 SG_ RTC_Year : 8|8@1+ (1,2000) [0|2255] ""  SBMU
 SG_ RTC_Month : 16|8@1+ (1,0) [0|255] ""  SBMU
 SG_ RTC_date : 24|8@1+ (1,0) [0|255] ""  SBMU
 SG_ RTC_Hour : 32|8@1+ (1,0) [0|255] ""  SBMU
 SG_ RTC_minute : 40|8@1+ (1,0) [0|255] ""  SBMU
 SG_ RTC_second : 48|8@1+ (1,0) [0|255] ""  SBMU
 SG_ RTC_CMD : 56|8@1+ (1,0) [0|255] ""  SBMU

BO_ 2149023649 M2S_RTC: 8 MBMU
 SG_ CRC_M2S_RTC : 0|8@1+ (1,0) [0|255] ""  SBMU
 SG_ RTC_Year : 8|8@1+ (1,2000) [0|2255] ""  SBMU
 SG_ RTC_Month : 16|8@1+ (1,0) [0|255] ""  SBMU
 SG_ RTC_date : 24|8@1+ (1,0) [0|255] ""  SBMU
 SG_ RTC_Hour : 32|8@1+ (1,0) [0|255] ""  SBMU
 SG_ RTC_minute : 40|8@1+ (1,0) [0|255] ""  SBMU
 SG_ RTC_second : 48|8@1+ (1,0) [0|255] ""  SBMU
 SG_ RTC_CMD : 56|8@1+ (1,0) [0|255] ""  SBMU

BO_ 2149023650 M2S_RTC: 8 MBMU
 SG_ CRC_M2S_RTC : 0|8@1+ (1,0) [0|255] ""  SBMU
 SG_ RTC_Year : 8|8@1+ (1,2000) [0|2255] ""  SBMU
 SG_ RTC_Month : 16|8@1+ (1,0) [0|255] ""  SBMU
 SG_ RTC_date : 24|8@1+ (1,0) [0|255] ""  SBMU
 SG_ RTC_Hour : 32|8@1+ (1,0) [0|255] ""  SBMU
 SG_ RTC_minute : 40|8@1+ (1,0) [0|255] ""  SBMU
 SG_ RTC_second : 48|8@1+ (1,0) [0|255] ""  SBMU
 SG_ RTC_CMD : 56|8@1+ (1,0) [0|255] ""  SBMU

BO_ 2149023651 M2S_RTC: 8 MBMU
 SG_ CRC_M2S_RTC : 0|8@1+ (1,0) [0|255] ""  SBMU
 SG_ RTC_Year : 8|8@1+ (1,2000) [0|2255] ""  SBMU
 SG_ RTC_Month : 16|8@1+ (1,0) [0|255] ""  SBMU
 SG_ RTC_date : 24|8@1+ (1,0) [0|255] ""  SBMU
 SG_ RTC_Hour : 32|8@1+ (1,0) [0|255] ""  SBMU
 SG_ RTC_minute : 40|8@1+ (1,0) [0|255] ""  SBMU
 SG_ RTC_second : 48|8@1+ (1,0) [0|255] ""  SBMU
 SG_ RTC_CMD : 56|8@1+ (1,0) [0|255] ""  SBMU

BO_ 2149023652 M2S_RTC: 8 MBMU
 SG_ CRC_M2S_RTC : 0|8@1+ (1,0) [0|255] ""  SBMU
 SG_ RTC_Year : 8|8@1+ (1,2000) [0|2255] ""  SBMU
 SG_ RTC_Month : 16|8@1+ (1,0) [0|255] ""  SBMU
 SG_ RTC_date : 24|8@1+ (1,0) [0|255] ""  SBMU
 SG_ RTC_Hour : 32|8@1+ (1,0) [0|255] ""  SBMU
 SG_ RTC_minute : 40|8@1+ (1,0) [0|255] ""  SBMU
 SG_ RTC_second : 48|8@1+ (1,0) [0|255] ""  SBMU
 SG_ RTC_CMD : 56|8@1+ (1,0) [0|255] ""  SBMU

BO_ 2149023653 M2S_RTC: 8 MBMU
 SG_ CRC_M2S_RTC : 0|8@1+ (1,0) [0|255] ""  SBMU
 SG_ RTC_Year : 8|8@1+ (1,2000) [0|2255] ""  SBMU
 SG_ RTC_Month : 16|8@1+ (1,0) [0|255] ""  SBMU
 SG_ RTC_date : 24|8@1+ (1,0) [0|255] ""  SBMU
 SG_ RTC_Hour : 32|8@1+ (1,0) [0|255] ""  SBMU
 SG_ RTC_minute : 40|8@1+ (1,0) [0|255] ""  SBMU
 SG_ RTC_second : 48|8@1+ (1,0) [0|255] ""  SBMU
 SG_ RTC_CMD : 56|8@1+ (1,0) [0|255] ""  SBMU

BO_ 2149023654 M2S_RTC: 8 MBMU
 SG_ CRC_M2S_RTC : 0|8@1+ (1,0) [0|255] ""  SBMU
 SG_ RTC_Year : 8|8@1+ (1,2000) [0|2255] ""  SBMU
 SG_ RTC_Month : 16|8@1+ (1,0) [0|255] ""  SBMU
 SG_ RTC_date : 24|8@1+ (1,0) [0|255] ""  SBMU
 SG_ RTC_Hour : 32|8@1+ (1,0) [0|255] ""  SBMU
 SG_ RTC_minute : 40|8@1+ (1,0) [0|255] ""  SBMU
 SG_ RTC_second : 48|8@1+ (1,0) [0|255] ""  SBMU
 SG_ RTC_CMD : 56|8@1+ (1,0) [0|255] ""  SBMU

BO_ 2149023655 M2S_RTC: 8 MBMU
 SG_ CRC_M2S_RTC : 0|8@1+ (1,0) [0|255] ""  SBMU
 SG_ RTC_Year : 8|8@1+ (1,2000) [0|2255] ""  SBMU
 SG_ RTC_Month : 16|8@1+ (1,0) [0|255] ""  SBMU
 SG_ RTC_date : 24|8@1+ (1,0) [0|255] ""  SBMU
 SG_ RTC_Hour : 32|8@1+ (1,0) [0|255] ""  SBMU
 SG_ RTC_minute : 40|8@1+ (1,0) [0|255] ""  SBMU
 SG_ RTC_second : 48|8@1+ (1,0) [0|255] ""  SBMU
 SG_ RTC_CMD : 56|8@1+ (1,0) [0|255] ""  SBMU

BO_ 2149023656 M2S_RTC: 8 MBMU
 SG_ CRC_M2S_RTC : 0|8@1+ (1,0) [0|255] ""  SBMU
 SG_ RTC_Year : 8|8@1+ (1,2000) [0|2255] ""  SBMU
 SG_ RTC_Month : 16|8@1+ (1,0) [0|255] ""  SBMU
 SG_ RTC_date : 24|8@1+ (1,0) [0|255] ""  SBMU
 SG_ RTC_Hour : 32|8@1+ (1,0) [0|255] ""  SBMU
 SG_ RTC_minute : 40|8@1+ (1,0) [0|255] ""  SBMU
 SG_ RTC_second : 48|8@1+ (1,0) [0|255] ""  SBMU
 SG_ RTC_CMD : 56|8@1+ (1,0) [0|255] ""  SBMU

BO_ 2149023657 M2S_RTC: 8 MBMU
 SG_ CRC_M2S_RTC : 0|8@1+ (1,0) [0|255] ""  SBMU
 SG_ RTC_Year : 8|8@1+ (1,2000) [0|2255] ""  SBMU
 SG_ RTC_Month : 16|8@1+ (1,0) [0|255] ""  SBMU
 SG_ RTC_date : 24|8@1+ (1,0) [0|255] ""  SBMU
 SG_ RTC_Hour : 32|8@1+ (1,0) [0|255] ""  SBMU
 SG_ RTC_minute : 40|8@1+ (1,0) [0|255] ""  SBMU
 SG_ RTC_second : 48|8@1+ (1,0) [0|255] ""  SBMU
 SG_ RTC_CMD : 56|8@1+ (1,0) [0|255] ""  SBMU

BO_ 2149023658 M2S_RTC: 8 MBMU
 SG_ CRC_M2S_RTC : 0|8@1+ (1,0) [0|255] ""  SBMU
 SG_ RTC_Year : 8|8@1+ (1,2000) [0|2255] ""  SBMU
 SG_ RTC_Month : 16|8@1+ (1,0) [0|255] ""  SBMU
 SG_ RTC_date : 24|8@1+ (1,0) [0|255] ""  SBMU
 SG_ RTC_Hour : 32|8@1+ (1,0) [0|255] ""  SBMU
 SG_ RTC_minute : 40|8@1+ (1,0) [0|255] ""  SBMU
 SG_ RTC_second : 48|8@1+ (1,0) [0|255] ""  SBMU
 SG_ RTC_CMD : 56|8@1+ (1,0) [0|255] ""  SBMU

BO_ 2149023659 M2S_RTC: 8 MBMU
 SG_ CRC_M2S_RTC : 0|8@1+ (1,0) [0|255] ""  SBMU
 SG_ RTC_Year : 8|8@1+ (1,2000) [0|2255] ""  SBMU
 SG_ RTC_Month : 16|8@1+ (1,0) [0|255] ""  SBMU
 SG_ RTC_date : 24|8@1+ (1,0) [0|255] ""  SBMU
 SG_ RTC_Hour : 32|8@1+ (1,0) [0|255] ""  SBMU
 SG_ RTC_minute : 40|8@1+ (1,0) [0|255] ""  SBMU
 SG_ RTC_second : 48|8@1+ (1,0) [0|255] ""  SBMU
 SG_ RTC_CMD : 56|8@1+ (1,0) [0|255] ""  SBMU

BO_ 2149023660 M2S_RTC: 8 MBMU
 SG_ CRC_M2S_RTC : 0|8@1+ (1,0) [0|255] ""  SBMU
 SG_ RTC_Year : 8|8@1+ (1,2000) [0|2255] ""  SBMU
 SG_ RTC_Month : 16|8@1+ (1,0) [0|255] ""  SBMU
 SG_ RTC_date : 24|8@1+ (1,0) [0|255] ""  SBMU
 SG_ RTC_Hour : 32|8@1+ (1,0) [0|255] ""  SBMU
 SG_ RTC_minute : 40|8@1+ (1,0) [0|255] ""  SBMU
 SG_ RTC_second : 48|8@1+ (1,0) [0|255] ""  SBMU
 SG_ RTC_CMD : 56|8@1+ (1,0) [0|255] ""  SBMU

BO_ 2149023661 M2S_RTC: 8 MBMU
 SG_ CRC_M2S_RTC : 0|8@1+ (1,0) [0|255] ""  SBMU
 SG_ RTC_Year : 8|8@1+ (1,2000) [0|2255] ""  SBMU
 SG_ RTC_Month : 16|8@1+ (1,0) [0|255] ""  SBMU
 SG_ RTC_date : 24|8@1+ (1,0) [0|255] ""  SBMU
 SG_ RTC_Hour : 32|8@1+ (1,0) [0|255] ""  SBMU
 SG_ RTC_minute : 40|8@1+ (1,0) [0|255] ""  SBMU
 SG_ RTC_second : 48|8@1+ (1,0) [0|255] ""  SBMU
 SG_ RTC_CMD : 56|8@1+ (1,0) [0|255] ""  SBMU

BO_ 2149023662 M2S_RTC: 8 MBMU
 SG_ CRC_M2S_RTC : 0|8@1+ (1,0) [0|255] ""  SBMU
 SG_ RTC_Year : 8|8@1+ (1,2000) [0|2255] ""  SBMU
 SG_ RTC_Month : 16|8@1+ (1,0) [0|255] ""  SBMU
 SG_ RTC_date : 24|8@1+ (1,0) [0|255] ""  SBMU
 SG_ RTC_Hour : 32|8@1+ (1,0) [0|255] ""  SBMU
 SG_ RTC_minute : 40|8@1+ (1,0) [0|255] ""  SBMU
 SG_ RTC_second : 48|8@1+ (1,0) [0|255] ""  SBMU
 SG_ RTC_CMD : 56|8@1+ (1,0) [0|255] ""  SBMU

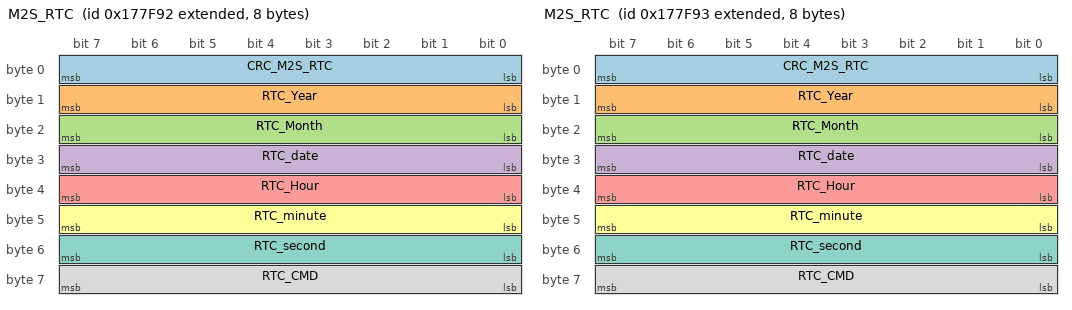
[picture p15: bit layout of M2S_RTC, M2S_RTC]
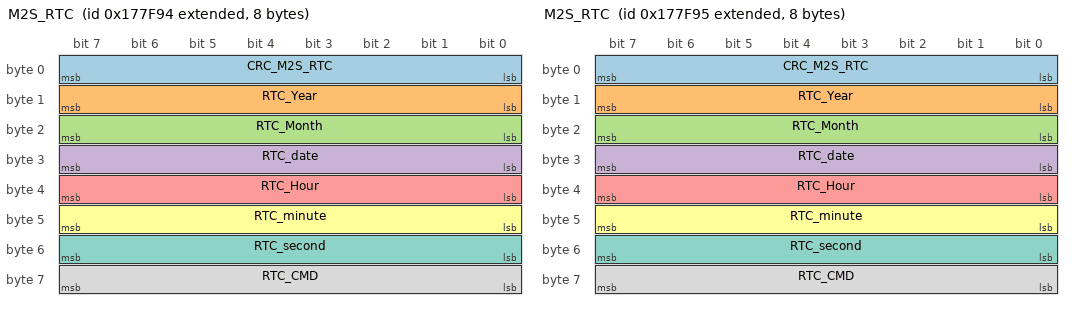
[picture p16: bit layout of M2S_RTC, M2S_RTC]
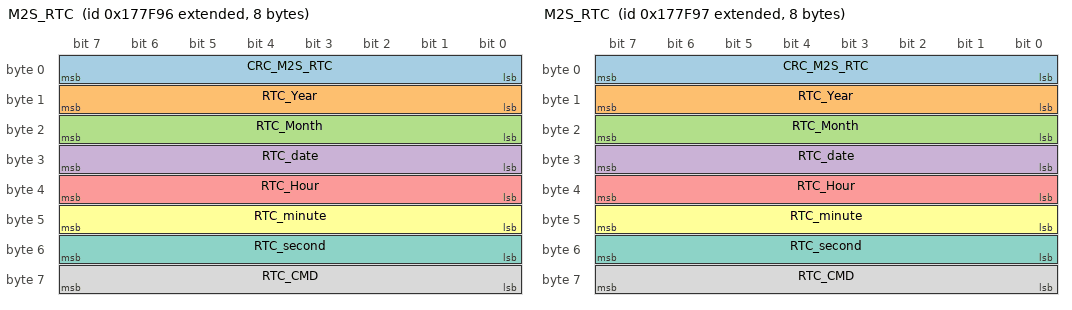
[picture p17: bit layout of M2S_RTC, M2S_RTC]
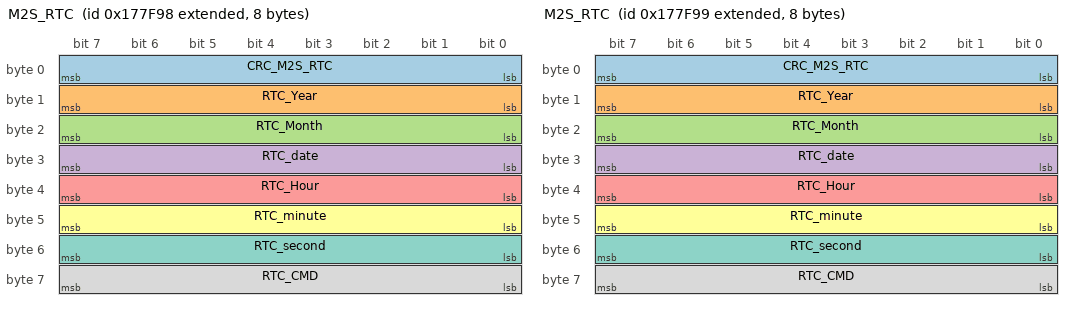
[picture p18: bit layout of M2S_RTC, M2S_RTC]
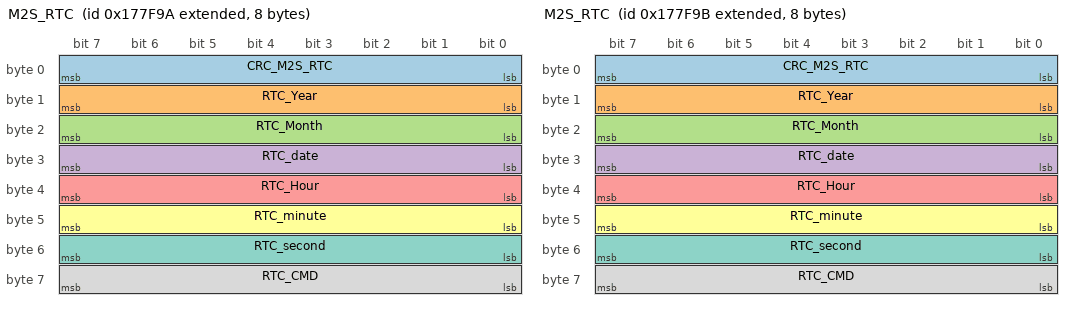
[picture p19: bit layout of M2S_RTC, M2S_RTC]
BO_ 2149023663 M2S_RTC: 8 MBMU
 SG_ CRC_M2S_RTC : 0|8@1+ (1,0) [0|255] ""  SBMU
 SG_ RTC_Year : 8|8@1+ (1,2000) [0|2255] ""  SBMU
 SG_ RTC_Month : 16|8@1+ (1,0) [0|255] ""  SBMU
 SG_ RTC_date : 24|8@1+ (1,0) [0|255] ""  SBMU
 SG_ RTC_Hour : 32|8@1+ (1,0) [0|255] ""  SBMU
 SG_ RTC_minute : 40|8@1+ (1,0) [0|255] ""  SBMU
 SG_ RTC_second : 48|8@1+ (1,0) [0|255] ""  SBMU
 SG_ RTC_CMD : 56|8@1+ (1,0) [0|255] ""  SBMU

BO_ 2433198830 P2M_Cfg6: 8 PC
 SG_ P2M_Cfg6_MBMU_data1 : 0|8@1+ (1,0) [0|255] ""  MBMU
 SG_ P2M_Cfg6_MBMU_data2 : 8|8@1+ (1,0) [0|255] ""  MBMU
 SG_ P2M_Cfg6_MBMU_data3 : 16|8@1+ (1,0) [0|255] ""  MBMU
 SG_ P2M_Cfg6_MBMU_data4 : 24|8@1+ (1,0) [0|255] ""  MBMU
 SG_ P2M_Cfg6_MBMU_data5 : 32|8@1+ (1,0) [0|255] ""  MBMU
 SG_ P2M_Cfg6_MBMU_data6 : 40|8@1+ (1,0) [0|255] ""  MBMU
 SG_ P2M_Cfg6_MBMU_data7 : 48|8@1+ (1,0) [0|255] ""  MBMU
 SG_ P2M_Cfg6_MBMU_data8 : 56|8@1+ (1,0) [0|255] ""  MBMU

BO_ 2417880641 S2P_Response__01: 8 SBMU
 SG_ S2P_Response_Byte1_01 : 0|8@1+ (1,0) [0|255] ""  PC
 SG_ S2P_Response_Byte2_01 : 8|8@1+ (1,0) [0|255] ""  PC
 SG_ S2P_Response_Byte3_01 : 16|8@1+ (1,0) [0|255] ""  PC
 SG_ S2P_Response_Byte4_01 : 24|8@1+ (1,0) [0|255] ""  PC
 SG_ S2P_Response_Byte5_01 : 32|8@1+ (1,0) [0|255] ""  PC
 SG_ S2P_Response_Byte6_01 : 40|8@1+ (1,0) [0|255] ""  PC
 SG_ S2P_Response_Byte7_01 : 48|8@1+ (1,0) [0|255] ""  PC
 SG_ S2P_Response_Byte8_01 : 56|8@1+ (1,0) [0|255] ""  PC

BO_ 2417880642 S2P_Response__02: 8 SBMU
 SG_ S2P_Response_Byte1_02 : 0|8@1+ (1,0) [0|255] ""  PC
 SG_ S2P_Response_Byte2_02 : 8|8@1+ (1,0) [0|255] ""  PC
 SG_ S2P_Response_Byte3_02 : 16|8@1+ (1,0) [0|255] ""  PC
 SG_ S2P_Response_Byte4_02 : 24|8@1+ (1,0) [0|255] ""  PC
 SG_ S2P_Response_Byte5_02 : 32|8@1+ (1,0) [0|255] ""  PC
 SG_ S2P_Response_Byte6_02 : 40|8@1+ (1,0) [0|255] ""  PC
 SG_ S2P_Response_Byte7_02 : 48|8@1+ (1,0) [0|255] ""  PC
 SG_ S2P_Response_Byte8_02 : 56|8@1+ (1,0) [0|255] ""  PC

BO_ 2417880643 S2P_Response__03: 8 SBMU
 SG_ S2P_Response_Byte1_03 : 0|8@1+ (1,0) [0|255] ""  PC
 SG_ S2P_Response_Byte2_03 : 8|8@1+ (1,0) [0|255] ""  PC
 SG_ S2P_Response_Byte3_03 : 16|8@1+ (1,0) [0|255] ""  PC
 SG_ S2P_Response_Byte4_03 : 24|8@1+ (1,0) [0|255] ""  PC
 SG_ S2P_Response_Byte5_03 : 32|8@1+ (1,0) [0|255] ""  PC
 SG_ S2P_Response_Byte6_03 : 40|8@1+ (1,0) [0|255] ""  PC
 SG_ S2P_Response_Byte7_03 : 48|8@1+ (1,0) [0|255] ""  PC
 SG_ S2P_Response_Byte8_03 : 56|8@1+ (1,0) [0|255] ""  PC

BO_ 2417880644 S2P_Response__04: 8 SBMU
 SG_ S2P_Response_Byte1_04 : 0|8@1+ (1,0) [0|255] ""  PC
 SG_ S2P_Response_Byte2_04 : 8|8@1+ (1,0) [0|255] ""  PC
 SG_ S2P_Response_Byte3_04 : 16|8@1+ (1,0) [0|255] ""  PC
 SG_ S2P_Response_Byte4_04 : 24|8@1+ (1,0) [0|255] ""  PC
 SG_ S2P_Response_Byte5_04 : 32|8@1+ (1,0) [0|255] ""  PC
 SG_ S2P_Response_Byte6_04 : 40|8@1+ (1,0) [0|255] ""  PC
 SG_ S2P_Response_Byte7_04 : 48|8@1+ (1,0) [0|255] ""  PC
 SG_ S2P_Response_Byte8_04 : 56|8@1+ (1,0) [0|255] ""  PC

BO_ 2417880645 S2P_Response__05: 8 SBMU
 SG_ S2P_Response_Byte1_05 : 0|8@1+ (1,0) [0|255] ""  PC
 SG_ S2P_Response_Byte2_05 : 8|8@1+ (1,0) [0|255] ""  PC
 SG_ S2P_Response_Byte3_05 : 16|8@1+ (1,0) [0|255] ""  PC
 SG_ S2P_Response_Byte4_05 : 24|8@1+ (1,0) [0|255] ""  PC
 SG_ S2P_Response_Byte5_05 : 32|8@1+ (1,0) [0|255] ""  PC
 SG_ S2P_Response_Byte6_05 : 40|8@1+ (1,0) [0|255] ""  PC
 SG_ S2P_Response_Byte7_05 : 48|8@1+ (1,0) [0|255] ""  PC
 SG_ S2P_Response_Byte8_05 : 56|8@1+ (1,0) [0|255] ""  PC

BO_ 2417880646 S2P_Response__06: 8 SBMU
 SG_ S2P_Response_Byte1_06 : 0|8@1+ (1,0) [0|255] ""  PC
 SG_ S2P_Response_Byte2_06 : 8|8@1+ (1,0) [0|255] ""  PC
 SG_ S2P_Response_Byte3_06 : 16|8@1+ (1,0) [0|255] ""  PC
 SG_ S2P_Response_Byte4_06 : 24|8@1+ (1,0) [0|255] ""  PC
 SG_ S2P_Response_Byte5_06 : 32|8@1+ (1,0) [0|255] ""  PC
 SG_ S2P_Response_Byte6_06 : 40|8@1+ (1,0) [0|255] ""  PC
 SG_ S2P_Response_Byte7_06 : 48|8@1+ (1,0) [0|255] ""  PC
 SG_ S2P_Response_Byte8_06 : 56|8@1+ (1,0) [0|255] ""  PC

BO_ 2417880647 S2P_Response__07: 8 SBMU
 SG_ S2P_Response_Byte1_07 : 0|8@1+ (1,0) [0|255] ""  PC
 SG_ S2P_Response_Byte2_07 : 8|8@1+ (1,0) [0|255] ""  PC
 SG_ S2P_Response_Byte3_07 : 16|8@1+ (1,0) [0|255] ""  PC
 SG_ S2P_Response_Byte4_07 : 24|8@1+ (1,0) [0|255] ""  PC
 SG_ S2P_Response_Byte5_07 : 32|8@1+ (1,0) [0|255] ""  PC
 SG_ S2P_Response_Byte6_07 : 40|8@1+ (1,0) [0|255] ""  PC
 SG_ S2P_Response_Byte7_07 : 48|8@1+ (1,0) [0|255] ""  PC
 SG_ S2P_Response_Byte8_07 : 56|8@1+ (1,0) [0|255] ""  PC

BO_ 2417880648 S2P_Response__08: 8 SBMU
 SG_ S2P_Response_Byte1_08 : 0|8@1+ (1,0) [0|255] ""  PC
 SG_ S2P_Response_Byte2_08 : 8|8@1+ (1,0) [0|255] ""  PC
 SG_ S2P_Response_Byte3_08 : 16|8@1+ (1,0) [0|255] ""  PC
 SG_ S2P_Response_Byte4_08 : 24|8@1+ (1,0) [0|255] ""  PC
 SG_ S2P_Response_Byte5_08 : 32|8@1+ (1,0) [0|255] ""  PC
 SG_ S2P_Response_Byte6_08 : 40|8@1+ (1,0) [0|255] ""  PC
 SG_ S2P_Response_Byte7_08 : 48|8@1+ (1,0) [0|255] ""  PC
 SG_ S2P_Response_Byte8_08 : 56|8@1+ (1,0) [0|255] ""  PC

BO_ 2417880649 S2P_Response__09: 8 SBMU
 SG_ S2P_Response_Byte1_09 : 0|8@1+ (1,0) [0|255] ""  PC
 SG_ S2P_Response_Byte2_09 : 8|8@1+ (1,0) [0|255] ""  PC
 SG_ S2P_Response_Byte3_09 : 16|8@1+ (1,0) [0|255] ""  PC
 SG_ S2P_Response_Byte4_09 : 24|8@1+ (1,0) [0|255] ""  PC
 SG_ S2P_Response_Byte5_09 : 32|8@1+ (1,0) [0|255] ""  PC
 SG_ S2P_Response_Byte6_09 : 40|8@1+ (1,0) [0|255] ""  PC
 SG_ S2P_Response_Byte7_09 : 48|8@1+ (1,0) [0|255] ""  PC
 SG_ S2P_Response_Byte8_09 : 56|8@1+ (1,0) [0|255] ""  PC

BO_ 2417880650 S2P_Response__10: 8 SBMU
 SG_ S2P_Response_Byte1_10 : 0|8@1+ (1,0) [0|255] ""  PC
 SG_ S2P_Response_Byte2_10 : 8|8@1+ (1,0) [0|255] ""  PC
 SG_ S2P_Response_Byte3_10 : 16|8@1+ (1,0) [0|255] ""  PC
 SG_ S2P_Response_Byte4_10 : 24|8@1+ (1,0) [0|255] ""  PC
 SG_ S2P_Response_Byte5_10 : 32|8@1+ (1,0) [0|255] ""  PC
 SG_ S2P_Response_Byte6_10 : 40|8@1+ (1,0) [0|255] ""  PC
 SG_ S2P_Response_Byte7_10 : 48|8@1+ (1,0) [0|255] ""  PC
 SG_ S2P_Response_Byte8_10 : 56|8@1+ (1,0) [0|255] ""  PC

BO_ 2417880651 S2P_Response__11: 8 SBMU
 SG_ S2P_Response_Byte1_11 : 0|8@1+ (1,0) [0|255] ""  PC
 SG_ S2P_Response_Byte2_11 : 8|8@1+ (1,0) [0|255] ""  PC
 SG_ S2P_Response_Byte3_11 : 16|8@1+ (1,0) [0|255] ""  PC
 SG_ S2P_Response_Byte4_11 : 24|8@1+ (1,0) [0|255] ""  PC
 SG_ S2P_Response_Byte5_11 : 32|8@1+ (1,0) [0|255] ""  PC
 SG_ S2P_Response_Byte6_11 : 40|8@1+ (1,0) [0|255] ""  PC
 SG_ S2P_Response_Byte7_11 : 48|8@1+ (1,0) [0|255] ""  PC
 SG_ S2P_Response_Byte8_11 : 56|8@1+ (1,0) [0|255] ""  PC

BO_ 2417880652 S2P_Response__12: 8 SBMU
 SG_ S2P_Response_Byte1_12 : 0|8@1+ (1,0) [0|255] ""  PC
 SG_ S2P_Response_Byte2_12 : 8|8@1+ (1,0) [0|255] ""  PC
 SG_ S2P_Response_Byte3_12 : 16|8@1+ (1,0) [0|255] ""  PC
 SG_ S2P_Response_Byte4_12 : 24|8@1+ (1,0) [0|255] ""  PC
 SG_ S2P_Response_Byte5_12 : 32|8@1+ (1,0) [0|255] ""  PC
 SG_ S2P_Response_Byte6_12 : 40|8@1+ (1,0) [0|255] ""  PC
 SG_ S2P_Response_Byte7_12 : 48|8@1+ (1,0) [0|255] ""  PC
 SG_ S2P_Response_Byte8_12 : 56|8@1+ (1,0) [0|255] ""  PC

BO_ 2417880653 S2P_Response__13: 8 SBMU
 SG_ S2P_Response_Byte1_13 : 0|8@1+ (1,0) [0|255] ""  PC
 SG_ S2P_Response_Byte2_13 : 8|8@1+ (1,0) [0|255] ""  PC
 SG_ S2P_Response_Byte3_13 : 16|8@1+ (1,0) [0|255] ""  PC
 SG_ S2P_Response_Byte4_13 : 24|8@1+ (1,0) [0|255] ""  PC
 SG_ S2P_Response_Byte5_13 : 32|8@1+ (1,0) [0|255] ""  PC
 SG_ S2P_Response_Byte6_13 : 40|8@1+ (1,0) [0|255] ""  PC
 SG_ S2P_Response_Byte7_13 : 48|8@1+ (1,0) [0|255] ""  PC
 SG_ S2P_Response_Byte8_13 : 56|8@1+ (1,0) [0|255] ""  PC

BO_ 2417880654 S2P_Response__14: 8 SBMU
 SG_ S2P_Response_Byte1_14 : 0|8@1+ (1,0) [0|255] ""  PC
 SG_ S2P_Response_Byte2_14 : 8|8@1+ (1,0) [0|255] ""  PC
 SG_ S2P_Response_Byte3_14 : 16|8@1+ (1,0) [0|255] ""  PC
 SG_ S2P_Response_Byte4_14 : 24|8@1+ (1,0) [0|255] ""  PC
 SG_ S2P_Response_Byte5_14 : 32|8@1+ (1,0) [0|255] ""  PC
 SG_ S2P_Response_Byte6_14 : 40|8@1+ (1,0) [0|255] ""  PC
 SG_ S2P_Response_Byte7_14 : 48|8@1+ (1,0) [0|255] ""  PC
 SG_ S2P_Response_Byte8_14 : 56|8@1+ (1,0) [0|255] ""  PC

BO_ 2417880655 S2P_Response__15: 8 SBMU
 SG_ S2P_Response_Byte1_15 : 0|8@1+ (1,0) [0|255] ""  PC
 SG_ S2P_Response_Byte2_15 : 8|8@1+ (1,0) [0|255] ""  PC
 SG_ S2P_Response_Byte3_15 : 16|8@1+ (1,0) [0|255] ""  PC
 SG_ S2P_Response_Byte4_15 : 24|8@1+ (1,0) [0|255] ""  PC
 SG_ S2P_Response_Byte5_15 : 32|8@1+ (1,0) [0|255] ""  PC
 SG_ S2P_Response_Byte6_15 : 40|8@1+ (1,0) [0|255] ""  PC
 SG_ S2P_Response_Byte7_15 : 48|8@1+ (1,0) [0|255] ""  PC
 SG_ S2P_Response_Byte8_15 : 56|8@1+ (1,0) [0|255] ""  PC

BO_ 2417880656 S2P_Response__16: 8 SBMU
 SG_ S2P_Response_Byte1_16 : 0|8@1+ (1,0) [0|255] ""  PC
 SG_ S2P_Response_Byte2_16 : 8|8@1+ (1,0) [0|255] ""  PC
 SG_ S2P_Response_Byte3_16 : 16|8@1+ (1,0) [0|255] ""  PC
 SG_ S2P_Response_Byte4_16 : 24|8@1+ (1,0) [0|255] ""  PC
 SG_ S2P_Response_Byte5_16 : 32|8@1+ (1,0) [0|255] ""  PC
 SG_ S2P_Response_Byte6_16 : 40|8@1+ (1,0) [0|255] ""  PC
 SG_ S2P_Response_Byte7_16 : 48|8@1+ (1,0) [0|255] ""  PC
 SG_ S2P_Response_Byte8_16 : 56|8@1+ (1,0) [0|255] ""  PC

BO_ 2417880657 S2P_Response__17: 8 SBMU
 SG_ S2P_Response_Byte1_17 : 0|8@1+ (1,0) [0|255] ""  PC
 SG_ S2P_Response_Byte2_17 : 8|8@1+ (1,0) [0|255] ""  PC
 SG_ S2P_Response_Byte3_17 : 16|8@1+ (1,0) [0|255] ""  PC
 SG_ S2P_Response_Byte4_17 : 24|8@1+ (1,0) [0|255] ""  PC
 SG_ S2P_Response_Byte5_17 : 32|8@1+ (1,0) [0|255] ""  PC
 SG_ S2P_Response_Byte6_17 : 40|8@1+ (1,0) [0|255] ""  PC
 SG_ S2P_Response_Byte7_17 : 48|8@1+ (1,0) [0|255] ""  PC
 SG_ S2P_Response_Byte8_17 : 56|8@1+ (1,0) [0|255] ""  PC

BO_ 2417880658 S2P_Response__18: 8 SBMU
 SG_ S2P_Response_Byte1_18 : 0|8@1+ (1,0) [0|255] ""  PC
 SG_ S2P_Response_Byte2_18 : 8|8@1+ (1,0) [0|255] ""  PC
 SG_ S2P_Response_Byte3_18 : 16|8@1+ (1,0) [0|255] ""  PC
 SG_ S2P_Response_Byte4_18 : 24|8@1+ (1,0) [0|255] ""  PC
 SG_ S2P_Response_Byte5_18 : 32|8@1+ (1,0) [0|255] ""  PC
 SG_ S2P_Response_Byte6_18 : 40|8@1+ (1,0) [0|255] ""  PC
 SG_ S2P_Response_Byte7_18 : 48|8@1+ (1,0) [0|255] ""  PC
 SG_ S2P_Response_Byte8_18 : 56|8@1+ (1,0) [0|255] ""  PC

BO_ 2417880659 S2P_Response__19: 8 SBMU
 SG_ S2P_Response_Byte1_19 : 0|8@1+ (1,0) [0|255] ""  PC
 SG_ S2P_Response_Byte2_19 : 8|8@1+ (1,0) [0|255] ""  PC
 SG_ S2P_Response_Byte3_19 : 16|8@1+ (1,0) [0|255] ""  PC
 SG_ S2P_Response_Byte4_19 : 24|8@1+ (1,0) [0|255] ""  PC
 SG_ S2P_Response_Byte5_19 : 32|8@1+ (1,0) [0|255] ""  PC
 SG_ S2P_Response_Byte6_19 : 40|8@1+ (1,0) [0|255] ""  PC
 SG_ S2P_Response_Byte7_19 : 48|8@1+ (1,0) [0|255] ""  PC
 SG_ S2P_Response_Byte8_19 : 56|8@1+ (1,0) [0|255] ""  PC

BO_ 2417880660 S2P_Response__20: 8 SBMU
 SG_ S2P_Response_Byte1_20 : 0|8@1+ (1,0) [0|255] ""  PC
 SG_ S2P_Response_Byte2_20 : 8|8@1+ (1,0) [0|255] ""  PC
 SG_ S2P_Response_Byte3_20 : 16|8@1+ (1,0) [0|255] ""  PC
 SG_ S2P_Response_Byte4_20 : 24|8@1+ (1,0) [0|255] ""  PC
 SG_ S2P_Response_Byte5_20 : 32|8@1+ (1,0) [0|255] ""  PC
 SG_ S2P_Response_Byte6_20 : 40|8@1+ (1,0) [0|255] ""  PC
 SG_ S2P_Response_Byte7_20 : 48|8@1+ (1,0) [0|255] ""  PC
 SG_ S2P_Response_Byte8_20 : 56|8@1+ (1,0) [0|255] ""  PC

BO_ 2417880661 S2P_Response__21: 8 SBMU
 SG_ S2P_Response_Byte1_21 : 0|8@1+ (1,0) [0|255] ""  PC
 SG_ S2P_Response_Byte2_21 : 8|8@1+ (1,0) [0|255] ""  PC
 SG_ S2P_Response_Byte3_21 : 16|8@1+ (1,0) [0|255] ""  PC
 SG_ S2P_Response_Byte4_21 : 24|8@1+ (1,0) [0|255] ""  PC
 SG_ S2P_Response_Byte5_21 : 32|8@1+ (1,0) [0|255] ""  PC
 SG_ S2P_Response_Byte6_21 : 40|8@1+ (1,0) [0|255] ""  PC
 SG_ S2P_Response_Byte7_21 : 48|8@1+ (1,0) [0|255] ""  PC
 SG_ S2P_Response_Byte8_21 : 56|8@1+ (1,0) [0|255] ""  PC

BO_ 2417880662 S2P_Response__22: 8 SBMU
 SG_ S2P_Response_Byte1_22 : 0|8@1+ (1,0) [0|255] ""  PC
 SG_ S2P_Response_Byte2_22 : 8|8@1+ (1,0) [0|255] ""  PC
 SG_ S2P_Response_Byte3_22 : 16|8@1+ (1,0) [0|255] ""  PC
 SG_ S2P_Response_Byte4_22 : 24|8@1+ (1,0) [0|255] ""  PC
 SG_ S2P_Response_Byte5_22 : 32|8@1+ (1,0) [0|255] ""  PC
 SG_ S2P_Response_Byte6_22 : 40|8@1+ (1,0) [0|255] ""  PC
 SG_ S2P_Response_Byte7_22 : 48|8@1+ (1,0) [0|255] ""  PC
 SG_ S2P_Response_Byte8_22 : 56|8@1+ (1,0) [0|255] ""  PC

BO_ 2417880663 S2P_Response__23: 8 SBMU
 SG_ S2P_Response_Byte1_23 : 0|8@1+ (1,0) [0|255] ""  PC
 SG_ S2P_Response_Byte2_23 : 8|8@1+ (1,0) [0|255] ""  PC
 SG_ S2P_Response_Byte3_23 : 16|8@1+ (1,0) [0|255] ""  PC
 SG_ S2P_Response_Byte4_23 : 24|8@1+ (1,0) [0|255] ""  PC
 SG_ S2P_Response_Byte5_23 : 32|8@1+ (1,0) [0|255] ""  PC
 SG_ S2P_Response_Byte6_23 : 40|8@1+ (1,0) [0|255] ""  PC
 SG_ S2P_Response_Byte7_23 : 48|8@1+ (1,0) [0|255] ""  PC
 SG_ S2P_Response_Byte8_23 : 56|8@1+ (1,0) [0|255] ""  PC

BO_ 2417880664 S2P_Response__24: 8 SBMU
 SG_ S2P_Response_Byte1_24 : 0|8@1+ (1,0) [0|255] ""  PC
 SG_ S2P_Response_Byte2_24 : 8|8@1+ (1,0) [0|255] ""  PC
 SG_ S2P_Response_Byte3_24 : 16|8@1+ (1,0) [0|255] ""  PC
 SG_ S2P_Response_Byte4_24 : 24|8@1+ (1,0) [0|255] ""  PC
 SG_ S2P_Response_Byte5_24 : 32|8@1+ (1,0) [0|255] ""  PC
 SG_ S2P_Response_Byte6_24 : 40|8@1+ (1,0) [0|255] ""  PC
 SG_ S2P_Response_Byte7_24 : 48|8@1+ (1,0) [0|255] ""  PC
 SG_ S2P_Response_Byte8_24 : 56|8@1+ (1,0) [0|255] ""  PC

BO_ 2417880665 S2P_Response__25: 8 SBMU
 SG_ S2P_Response_Byte1_25 : 0|8@1+ (1,0) [0|255] ""  PC
 SG_ S2P_Response_Byte2_25 : 8|8@1+ (1,0) [0|255] ""  PC
 SG_ S2P_Response_Byte3_25 : 16|8@1+ (1,0) [0|255] ""  PC
 SG_ S2P_Response_Byte4_25 : 24|8@1+ (1,0) [0|255] ""  PC
 SG_ S2P_Response_Byte5_25 : 32|8@1+ (1,0) [0|255] ""  PC
 SG_ S2P_Response_Byte6_25 : 40|8@1+ (1,0) [0|255] ""  PC
 SG_ S2P_Response_Byte7_25 : 48|8@1+ (1,0) [0|255] ""  PC
 SG_ S2P_Response_Byte8_25 : 56|8@1+ (1,0) [0|255] ""  PC

BO_ 2417880666 S2P_Response__26: 8 SBMU
 SG_ S2P_Response_Byte1_26 : 0|8@1+ (1,0) [0|255] ""  PC
 SG_ S2P_Response_Byte2_26 : 8|8@1+ (1,0) [0|255] ""  PC
 SG_ S2P_Response_Byte3_26 : 16|8@1+ (1,0) [0|255] ""  PC
 SG_ S2P_Response_Byte4_26 : 24|8@1+ (1,0) [0|255] ""  PC
 SG_ S2P_Response_Byte5_26 : 32|8@1+ (1,0) [0|255] ""  PC
 SG_ S2P_Response_Byte6_26 : 40|8@1+ (1,0) [0|255] ""  PC
 SG_ S2P_Response_Byte7_26 : 48|8@1+ (1,0) [0|255] ""  PC
 SG_ S2P_Response_Byte8_26 : 56|8@1+ (1,0) [0|255] ""  PC

BO_ 2417880667 S2P_Response__27: 8 SBMU
 SG_ S2P_Response_Byte1_27 : 0|8@1+ (1,0) [0|255] ""  PC
 SG_ S2P_Response_Byte2_27 : 8|8@1+ (1,0) [0|255] ""  PC
 SG_ S2P_Response_Byte3_27 : 16|8@1+ (1,0) [0|255] ""  PC
 SG_ S2P_Response_Byte4_27 : 24|8@1+ (1,0) [0|255] ""  PC
 SG_ S2P_Response_Byte5_27 : 32|8@1+ (1,0) [0|255] ""  PC
 SG_ S2P_Response_Byte6_27 : 40|8@1+ (1,0) [0|255] ""  PC
 SG_ S2P_Response_Byte7_27 : 48|8@1+ (1,0) [0|255] ""  PC
 SG_ S2P_Response_Byte8_27 : 56|8@1+ (1,0) [0|255] ""  PC

BO_ 2417880668 S2P_Response__28: 8 SBMU
 SG_ S2P_Response_Byte1_28 : 0|8@1+ (1,0) [0|255] ""  PC
 SG_ S2P_Response_Byte2_28 : 8|8@1+ (1,0) [0|255] ""  PC
 SG_ S2P_Response_Byte3_28 : 16|8@1+ (1,0) [0|255] ""  PC
 SG_ S2P_Response_Byte4_28 : 24|8@1+ (1,0) [0|255] ""  PC
 SG_ S2P_Response_Byte5_28 : 32|8@1+ (1,0) [0|255] ""  PC
 SG_ S2P_Response_Byte6_28 : 40|8@1+ (1,0) [0|255] ""  PC
 SG_ S2P_Response_Byte7_28 : 48|8@1+ (1,0) [0|255] ""  PC
 SG_ S2P_Response_Byte8_28 : 56|8@1+ (1,0) [0|255] ""  PC

BO_ 2417880669 S2P_Response__29: 8 SBMU
 SG_ S2P_Response_Byte1_29 : 0|8@1+ (1,0) [0|255] ""  PC
 SG_ S2P_Response_Byte2_29 : 8|8@1+ (1,0) [0|255] ""  PC
 SG_ S2P_Response_Byte3_29 : 16|8@1+ (1,0) [0|255] ""  PC
 SG_ S2P_Response_Byte4_29 : 24|8@1+ (1,0) [0|255] ""  PC
 SG_ S2P_Response_Byte5_29 : 32|8@1+ (1,0) [0|255] ""  PC
 SG_ S2P_Response_Byte6_29 : 40|8@1+ (1,0) [0|255] ""  PC
 SG_ S2P_Response_Byte7_29 : 48|8@1+ (1,0) [0|255] ""  PC
 SG_ S2P_Response_Byte8_29 : 56|8@1+ (1,0) [0|255] ""  PC

BO_ 2417880670 S2P_Response__30: 8 SBMU
 SG_ S2P_Response_Byte1_30 : 0|8@1+ (1,0) [0|255] ""  PC
 SG_ S2P_Response_Byte2_30 : 8|8@1+ (1,0) [0|255] ""  PC
 SG_ S2P_Response_Byte3_30 : 16|8@1+ (1,0) [0|255] ""  PC
 SG_ S2P_Response_Byte4_30 : 24|8@1+ (1,0) [0|255] ""  PC
 SG_ S2P_Response_Byte5_30 : 32|8@1+ (1,0) [0|255] ""  PC
 SG_ S2P_Response_Byte6_30 : 40|8@1+ (1,0) [0|255] ""  PC
 SG_ S2P_Response_Byte7_30 : 48|8@1+ (1,0) [0|255] ""  PC
 SG_ S2P_Response_Byte8_30 : 56|8@1+ (1,0) [0|255] ""  PC

BO_ 2417880671 S2P_Response__31: 8 SBMU
 SG_ S2P_Response_Byte1_31 : 0|8@1+ (1,0) [0|255] ""  PC
 SG_ S2P_Response_Byte2_31 : 8|8@1+ (1,0) [0|255] ""  PC
 SG_ S2P_Response_Byte3_31 : 16|8@1+ (1,0) [0|255] ""  PC
 SG_ S2P_Response_Byte4_31 : 24|8@1+ (1,0) [0|255] ""  PC
 SG_ S2P_Response_Byte5_31 : 32|8@1+ (1,0) [0|255] ""  PC
 SG_ S2P_Response_Byte6_31 : 40|8@1+ (1,0) [0|255] ""  PC
 SG_ S2P_Response_Byte7_31 : 48|8@1+ (1,0) [0|255] ""  PC
 SG_ S2P_Response_Byte8_31 : 56|8@1+ (1,0) [0|255] ""  PC

BO_ 2417880672 S2P_Response__32: 8 SBMU
 SG_ S2P_Response_Byte1_32 : 0|8@1+ (1,0) [0|255] ""  PC
 SG_ S2P_Response_Byte2_32 : 8|8@1+ (1,0) [0|255] ""  PC
 SG_ S2P_Response_Byte3_32 : 16|8@1+ (1,0) [0|255] ""  PC
 SG_ S2P_Response_Byte4_32 : 24|8@1+ (1,0) [0|255] ""  PC
 SG_ S2P_Response_Byte5_32 : 32|8@1+ (1,0) [0|255] ""  PC
 SG_ S2P_Response_Byte6_32 : 40|8@1+ (1,0) [0|255] ""  PC
 SG_ S2P_Response_Byte7_32 : 48|8@1+ (1,0) [0|255] ""  PC
 SG_ S2P_Response_Byte8_32 : 56|8@1+ (1,0) [0|255] ""  PC

BO_ 2417880673 S2P_Response__33: 8 SBMU
 SG_ S2P_Response_Byte1_33 : 0|8@1+ (1,0) [0|255] ""  PC
 SG_ S2P_Response_Byte2_33 : 8|8@1+ (1,0) [0|255] ""  PC
 SG_ S2P_Response_Byte3_33 : 16|8@1+ (1,0) [0|255] ""  PC
 SG_ S2P_Response_Byte4_33 : 24|8@1+ (1,0) [0|255] ""  PC
 SG_ S2P_Response_Byte5_33 : 32|8@1+ (1,0) [0|255] ""  PC
 SG_ S2P_Response_Byte6_33 : 40|8@1+ (1,0) [0|255] ""  PC
 SG_ S2P_Response_Byte7_33 : 48|8@1+ (1,0) [0|255] ""  PC
 SG_ S2P_Response_Byte8_33 : 56|8@1+ (1,0) [0|255] ""  PC

BO_ 2417880674 S2P_Response__34: 8 SBMU
 SG_ S2P_Response_Byte1_34 : 0|8@1+ (1,0) [0|255] ""  PC
 SG_ S2P_Response_Byte2_34 : 8|8@1+ (1,0) [0|255] ""  PC
 SG_ S2P_Response_Byte3_34 : 16|8@1+ (1,0) [0|255] ""  PC
 SG_ S2P_Response_Byte4_34 : 24|8@1+ (1,0) [0|255] ""  PC
 SG_ S2P_Response_Byte5_34 : 32|8@1+ (1,0) [0|255] ""  PC
 SG_ S2P_Response_Byte6_34 : 40|8@1+ (1,0) [0|255] ""  PC
 SG_ S2P_Response_Byte7_34 : 48|8@1+ (1,0) [0|255] ""  PC
 SG_ S2P_Response_Byte8_34 : 56|8@1+ (1,0) [0|255] ""  PC

BO_ 2417880675 S2P_Response__35: 8 SBMU
 SG_ S2P_Response_Byte1_35 : 0|8@1+ (1,0) [0|255] ""  PC
 SG_ S2P_Response_Byte2_35 : 8|8@1+ (1,0) [0|255] ""  PC
 SG_ S2P_Response_Byte3_35 : 16|8@1+ (1,0) [0|255] ""  PC
 SG_ S2P_Response_Byte4_35 : 24|8@1+ (1,0) [0|255] ""  PC
 SG_ S2P_Response_Byte5_35 : 32|8@1+ (1,0) [0|255] ""  PC
 SG_ S2P_Response_Byte6_35 : 40|8@1+ (1,0) [0|255] ""  PC
 SG_ S2P_Response_Byte7_35 : 48|8@1+ (1,0) [0|255] ""  PC
 SG_ S2P_Response_Byte8_35 : 56|8@1+ (1,0) [0|255] ""  PC

BO_ 2417880676 S2P_Response__36: 8 SBMU
 SG_ S2P_Response_Byte1_36 : 0|8@1+ (1,0) [0|255] ""  PC
 SG_ S2P_Response_Byte2_36 : 8|8@1+ (1,0) [0|255] ""  PC
 SG_ S2P_Response_Byte3_36 : 16|8@1+ (1,0) [0|255] ""  PC
 SG_ S2P_Response_Byte4_36 : 24|8@1+ (1,0) [0|255] ""  PC
 SG_ S2P_Response_Byte5_36 : 32|8@1+ (1,0) [0|255] ""  PC
 SG_ S2P_Response_Byte6_36 : 40|8@1+ (1,0) [0|255] ""  PC
 SG_ S2P_Response_Byte7_36 : 48|8@1+ (1,0) [0|255] ""  PC
 SG_ S2P_Response_Byte8_36 : 56|8@1+ (1,0) [0|255] ""  PC

BO_ 2417880677 S2P_Response__37: 8 SBMU
 SG_ S2P_Response_Byte1_37 : 0|8@1+ (1,0) [0|255] ""  PC
 SG_ S2P_Response_Byte2_37 : 8|8@1+ (1,0) [0|255] ""  PC
 SG_ S2P_Response_Byte3_37 : 16|8@1+ (1,0) [0|255] ""  PC
 SG_ S2P_Response_Byte4_37 : 24|8@1+ (1,0) [0|255] ""  PC
 SG_ S2P_Response_Byte5_37 : 32|8@1+ (1,0) [0|255] ""  PC
 SG_ S2P_Response_Byte6_37 : 40|8@1+ (1,0) [0|255] ""  PC
 SG_ S2P_Response_Byte7_37 : 48|8@1+ (1,0) [0|255] ""  PC
 SG_ S2P_Response_Byte8_37 : 56|8@1+ (1,0) [0|255] ""  PC

BO_ 2417880678 S2P_Response__38: 8 SBMU
 SG_ S2P_Response_Byte1_38 : 0|8@1+ (1,0) [0|255] ""  PC
 SG_ S2P_Response_Byte2_38 : 8|8@1+ (1,0) [0|255] ""  PC
 SG_ S2P_Response_Byte3_38 : 16|8@1+ (1,0) [0|255] ""  PC
 SG_ S2P_Response_Byte4_38 : 24|8@1+ (1,0) [0|255] ""  PC
 SG_ S2P_Response_Byte5_38 : 32|8@1+ (1,0) [0|255] ""  PC
 SG_ S2P_Response_Byte6_38 : 40|8@1+ (1,0) [0|255] ""  PC
 SG_ S2P_Response_Byte7_38 : 48|8@1+ (1,0) [0|255] ""  PC
 SG_ S2P_Response_Byte8_38 : 56|8@1+ (1,0) [0|255] ""  PC

BO_ 2417880679 S2P_Response__39: 8 SBMU
 SG_ S2P_Response_Byte1_39 : 0|8@1+ (1,0) [0|255] ""  PC
 SG_ S2P_Response_Byte2_39 : 8|8@1+ (1,0) [0|255] ""  PC
 SG_ S2P_Response_Byte3_39 : 16|8@1+ (1,0) [0|255] ""  PC
 SG_ S2P_Response_Byte4_39 : 24|8@1+ (1,0) [0|255] ""  PC
 SG_ S2P_Response_Byte5_39 : 32|8@1+ (1,0) [0|255] ""  PC
 SG_ S2P_Response_Byte6_39 : 40|8@1+ (1,0) [0|255] ""  PC
 SG_ S2P_Response_Byte7_39 : 48|8@1+ (1,0) [0|255] ""  PC
 SG_ S2P_Response_Byte8_39 : 56|8@1+ (1,0) [0|255] ""  PC

BO_ 2417880680 S2P_Response__40: 8 SBMU
 SG_ S2P_Response_Byte1_40 : 0|8@1+ (1,0) [0|255] ""  PC
 SG_ S2P_Response_Byte2_40 : 8|8@1+ (1,0) [0|255] ""  PC
 SG_ S2P_Response_Byte3_40 : 16|8@1+ (1,0) [0|255] ""  PC
 SG_ S2P_Response_Byte4_40 : 24|8@1+ (1,0) [0|255] ""  PC
 SG_ S2P_Response_Byte5_40 : 32|8@1+ (1,0) [0|255] ""  PC
 SG_ S2P_Response_Byte6_40 : 40|8@1+ (1,0) [0|255] ""  PC
 SG_ S2P_Response_Byte7_40 : 48|8@1+ (1,0) [0|255] ""  PC
 SG_ S2P_Response_Byte8_40 : 56|8@1+ (1,0) [0|255] ""  PC

BO_ 2417880681 S2P_Response__41: 8 SBMU
 SG_ S2P_Response_Byte1_41 : 0|8@1+ (1,0) [0|255] ""  PC
 SG_ S2P_Response_Byte2_41 : 8|8@1+ (1,0) [0|255] ""  PC
 SG_ S2P_Response_Byte3_41 : 16|8@1+ (1,0) [0|255] ""  PC
 SG_ S2P_Response_Byte4_41 : 24|8@1+ (1,0) [0|255] ""  PC
 SG_ S2P_Response_Byte5_41 : 32|8@1+ (1,0) [0|255] ""  PC
 SG_ S2P_Response_Byte6_41 : 40|8@1+ (1,0) [0|255] ""  PC
 SG_ S2P_Response_Byte7_41 : 48|8@1+ (1,0) [0|255] ""  PC
 SG_ S2P_Response_Byte8_41 : 56|8@1+ (1,0) [0|255] ""  PC

BO_ 2417880682 S2P_Response__42: 8 SBMU
 SG_ S2P_Response_Byte1_42 : 0|8@1+ (1,0) [0|255] ""  PC
 SG_ S2P_Response_Byte2_42 : 8|8@1+ (1,0) [0|255] ""  PC
 SG_ S2P_Response_Byte3_42 : 16|8@1+ (1,0) [0|255] ""  PC
 SG_ S2P_Response_Byte4_42 : 24|8@1+ (1,0) [0|255] ""  PC
 SG_ S2P_Response_Byte5_42 : 32|8@1+ (1,0) [0|255] ""  PC
 SG_ S2P_Response_Byte6_42 : 40|8@1+ (1,0) [0|255] ""  PC
 SG_ S2P_Response_Byte7_42 : 48|8@1+ (1,0) [0|255] ""  PC
 SG_ S2P_Response_Byte8_42 : 56|8@1+ (1,0) [0|255] ""  PC

BO_ 2417880683 S2P_Response__43: 8 SBMU
 SG_ S2P_Response_Byte1_43 : 0|8@1+ (1,0) [0|255] ""  PC
 SG_ S2P_Response_Byte2_43 : 8|8@1+ (1,0) [0|255] ""  PC
 SG_ S2P_Response_Byte3_43 : 16|8@1+ (1,0) [0|255] ""  PC
 SG_ S2P_Response_Byte4_43 : 24|8@1+ (1,0) [0|255] ""  PC
 SG_ S2P_Response_Byte5_43 : 32|8@1+ (1,0) [0|255] ""  PC
 SG_ S2P_Response_Byte6_43 : 40|8@1+ (1,0) [0|255] ""  PC
 SG_ S2P_Response_Byte7_43 : 48|8@1+ (1,0) [0|255] ""  PC
 SG_ S2P_Response_Byte8_43 : 56|8@1+ (1,0) [0|255] ""  PC

BO_ 2417880684 S2P_Response__44: 8 SBMU
 SG_ S2P_Response_Byte1_44 : 0|8@1+ (1,0) [0|255] ""  PC
 SG_ S2P_Response_Byte2_44 : 8|8@1+ (1,0) [0|255] ""  PC
 SG_ S2P_Response_Byte3_44 : 16|8@1+ (1,0) [0|255] ""  PC
 SG_ S2P_Response_Byte4_44 : 24|8@1+ (1,0) [0|255] ""  PC
 SG_ S2P_Response_Byte5_44 : 32|8@1+ (1,0) [0|255] ""  PC
 SG_ S2P_Response_Byte6_44 : 40|8@1+ (1,0) [0|255] ""  PC
 SG_ S2P_Response_Byte7_44 : 48|8@1+ (1,0) [0|255] ""  PC
 SG_ S2P_Response_Byte8_44 : 56|8@1+ (1,0) [0|255] ""  PC

BO_ 2417880685 S2P_Response__45: 8 SBMU
 SG_ S2P_Response_Byte1_45 : 0|8@1+ (1,0) [0|255] ""  PC
 SG_ S2P_Response_Byte2_45 : 8|8@1+ (1,0) [0|255] ""  PC
 SG_ S2P_Response_Byte3_45 : 16|8@1+ (1,0) [0|255] ""  PC
 SG_ S2P_Response_Byte4_45 : 24|8@1+ (1,0) [0|255] ""  PC
 SG_ S2P_Response_Byte5_45 : 32|8@1+ (1,0) [0|255] ""  PC
 SG_ S2P_Response_Byte6_45 : 40|8@1+ (1,0) [0|255] ""  PC
 SG_ S2P_Response_Byte7_45 : 48|8@1+ (1,0) [0|255] ""  PC
 SG_ S2P_Response_Byte8_45 : 56|8@1+ (1,0) [0|255] ""  PC

BO_ 2417880686 S2P_Response__46: 8 SBMU
 SG_ S2P_Response_Byte1_46 : 0|8@1+ (1,0) [0|255] ""  PC
 SG_ S2P_Response_Byte2_46 : 8|8@1+ (1,0) [0|255] ""  PC
 SG_ S2P_Response_Byte3_46 : 16|8@1+ (1,0) [0|255] ""  PC
 SG_ S2P_Response_Byte4_46 : 24|8@1+ (1,0) [0|255] ""  PC
 SG_ S2P_Response_Byte5_46 : 32|8@1+ (1,0) [0|255] ""  PC
 SG_ S2P_Response_Byte6_46 : 40|8@1+ (1,0) [0|255] ""  PC
 SG_ S2P_Response_Byte7_46 : 48|8@1+ (1,0) [0|255] ""  PC
 SG_ S2P_Response_Byte8_46 : 56|8@1+ (1,0) [0|255] ""  PC

BO_ 2417880687 S2P_Response__47: 8 SBMU
 SG_ S2P_Response_Byte1_47 : 0|8@1+ (1,0) [0|255] ""  PC
 SG_ S2P_Response_Byte2_47 : 8|8@1+ (1,0) [0|255] ""  PC
 SG_ S2P_Response_Byte3_47 : 16|8@1+ (1,0) [0|255] ""  PC
 SG_ S2P_Response_Byte4_47 : 24|8@1+ (1,0) [0|255] ""  PC
 SG_ S2P_Response_Byte5_47 : 32|8@1+ (1,0) [0|255] ""  PC
 SG_ S2P_Response_Byte6_47 : 40|8@1+ (1,0) [0|255] ""  PC
 SG_ S2P_Response_Byte7_47 : 48|8@1+ (1,0) [0|255] ""  PC
 SG_ S2P_Response_Byte8_47 : 56|8@1+ (1,0) [0|255] ""  PC

BO_ 2417880688 S2P_Response__48: 8 SBMU
 SG_ S2P_Response_Byte1_48 : 0|8@1+ (1,0) [0|255] ""  PC
 SG_ S2P_Response_Byte2_48 : 8|8@1+ (1,0) [0|255] ""  PC
 SG_ S2P_Response_Byte3_48 : 16|8@1+ (1,0) [0|255] ""  PC
 SG_ S2P_Response_Byte4_48 : 24|8@1+ (1,0) [0|255] ""  PC
 SG_ S2P_Response_Byte5_48 : 32|8@1+ (1,0) [0|255] ""  PC
 SG_ S2P_Response_Byte6_48 : 40|8@1+ (1,0) [0|255] ""  PC
 SG_ S2P_Response_Byte7_48 : 48|8@1+ (1,0) [0|255] ""  PC
 SG_ S2P_Response_Byte8_48 : 56|8@1+ (1,0) [0|255] ""  PC

BO_ 2417880689 S2P_Response__49: 8 SBMU
 SG_ S2P_Response_Byte1_49 : 0|8@1+ (1,0) [0|255] ""  PC
 SG_ S2P_Response_Byte2_49 : 8|8@1+ (1,0) [0|255] ""  PC
 SG_ S2P_Response_Byte3_49 : 16|8@1+ (1,0) [0|255] ""  PC
 SG_ S2P_Response_Byte4_49 : 24|8@1+ (1,0) [0|255] ""  PC
 SG_ S2P_Response_Byte5_49 : 32|8@1+ (1,0) [0|255] ""  PC
 SG_ S2P_Response_Byte6_49 : 40|8@1+ (1,0) [0|255] ""  PC
 SG_ S2P_Response_Byte7_49 : 48|8@1+ (1,0) [0|255] ""  PC
 SG_ S2P_Response_Byte8_49 : 56|8@1+ (1,0) [0|255] ""  PC

BO_ 2417880690 S2P_Response__50: 8 SBMU
 SG_ S2P_Response_Byte1_50 : 0|8@1+ (1,0) [0|255] ""  PC
 SG_ S2P_Response_Byte2_50 : 8|8@1+ (1,0) [0|255] ""  PC
 SG_ S2P_Response_Byte3_50 : 16|8@1+ (1,0) [0|255] ""  PC
 SG_ S2P_Response_Byte4_50 : 24|8@1+ (1,0) [0|255] ""  PC
 SG_ S2P_Response_Byte5_50 : 32|8@1+ (1,0) [0|255] ""  PC
 SG_ S2P_Response_Byte6_50 : 40|8@1+ (1,0) [0|255] ""  PC
 SG_ S2P_Response_Byte7_50 : 48|8@1+ (1,0) [0|255] ""  PC
 SG_ S2P_Response_Byte8_50 : 56|8@1+ (1,0) [0|255] ""  PC

BO_ 2417880691 S2P_Response__51: 8 SBMU
 SG_ S2P_Response_Byte1_51 : 0|8@1+ (1,0) [0|255] ""  PC
 SG_ S2P_Response_Byte2_51 : 8|8@1+ (1,0) [0|255] ""  PC
 SG_ S2P_Response_Byte3_51 : 16|8@1+ (1,0) [0|255] ""  PC
 SG_ S2P_Response_Byte4_51 : 24|8@1+ (1,0) [0|255] ""  PC
 SG_ S2P_Response_Byte5_51 : 32|8@1+ (1,0) [0|255] ""  PC
 SG_ S2P_Response_Byte6_51 : 40|8@1+ (1,0) [0|255] ""  PC
 SG_ S2P_Response_Byte7_51 : 48|8@1+ (1,0) [0|255] ""  PC
 SG_ S2P_Response_Byte8_51 : 56|8@1+ (1,0) [0|255] ""  PC

BO_ 2417880692 S2P_Response__52: 8 SBMU
 SG_ S2P_Response_Byte1_52 : 0|8@1+ (1,0) [0|255] ""  PC
 SG_ S2P_Response_Byte2_52 : 8|8@1+ (1,0) [0|255] ""  PC
 SG_ S2P_Response_Byte3_52 : 16|8@1+ (1,0) [0|255] ""  PC
 SG_ S2P_Response_Byte4_52 : 24|8@1+ (1,0) [0|255] ""  PC
 SG_ S2P_Response_Byte5_52 : 32|8@1+ (1,0) [0|255] ""  PC
 SG_ S2P_Response_Byte6_52 : 40|8@1+ (1,0) [0|255] ""  PC
 SG_ S2P_Response_Byte7_52 : 48|8@1+ (1,0) [0|255] ""  PC
 SG_ S2P_Response_Byte8_52 : 56|8@1+ (1,0) [0|255] ""  PC

BO_ 2417880693 S2P_Response__53: 8 SBMU
 SG_ S2P_Response_Byte1_53 : 0|8@1+ (1,0) [0|255] ""  PC
 SG_ S2P_Response_Byte2_53 : 8|8@1+ (1,0) [0|255] ""  PC
 SG_ S2P_Response_Byte3_53 : 16|8@1+ (1,0) [0|255] ""  PC
 SG_ S2P_Response_Byte4_53 : 24|8@1+ (1,0) [0|255] ""  PC
 SG_ S2P_Response_Byte5_53 : 32|8@1+ (1,0) [0|255] ""  PC
 SG_ S2P_Response_Byte6_53 : 40|8@1+ (1,0) [0|255] ""  PC
 SG_ S2P_Response_Byte7_53 : 48|8@1+ (1,0) [0|255] ""  PC
 SG_ S2P_Response_Byte8_53 : 56|8@1+ (1,0) [0|255] ""  PC

BO_ 2417880694 S2P_Response__54: 8 SBMU
 SG_ S2P_Response_Byte1_54 : 0|8@1+ (1,0) [0|255] ""  PC
 SG_ S2P_Response_Byte2_54 : 8|8@1+ (1,0) [0|255] ""  PC
 SG_ S2P_Response_Byte3_54 : 16|8@1+ (1,0) [0|255] ""  PC
 SG_ S2P_Response_Byte4_54 : 24|8@1+ (1,0) [0|255] ""  PC
 SG_ S2P_Response_Byte5_54 : 32|8@1+ (1,0) [0|255] ""  PC
 SG_ S2P_Response_Byte6_54 : 40|8@1+ (1,0) [0|255] ""  PC
 SG_ S2P_Response_Byte7_54 : 48|8@1+ (1,0) [0|255] ""  PC
 SG_ S2P_Response_Byte8_54 : 56|8@1+ (1,0) [0|255] ""  PC

BO_ 2417880695 S2P_Response__55: 8 SBMU
 SG_ S2P_Response_Byte1_55 : 0|8@1+ (1,0) [0|255] ""  PC
 SG_ S2P_Response_Byte2_55 : 8|8@1+ (1,0) [0|255] ""  PC
 SG_ S2P_Response_Byte3_55 : 16|8@1+ (1,0) [0|255] ""  PC
 SG_ S2P_Response_Byte4_55 : 24|8@1+ (1,0) [0|255] ""  PC
 SG_ S2P_Response_Byte5_55 : 32|8@1+ (1,0) [0|255] ""  PC
 SG_ S2P_Response_Byte6_55 : 40|8@1+ (1,0) [0|255] ""  PC
 SG_ S2P_Response_Byte7_55 : 48|8@1+ (1,0) [0|255] ""  PC
 SG_ S2P_Response_Byte8_55 : 56|8@1+ (1,0) [0|255] ""  PC

BO_ 2417880696 S2P_Response__56: 8 SBMU
 SG_ S2P_Response_Byte1_56 : 0|8@1+ (1,0) [0|255] ""  PC
 SG_ S2P_Response_Byte2_56 : 8|8@1+ (1,0) [0|255] ""  PC
 SG_ S2P_Response_Byte3_56 : 16|8@1+ (1,0) [0|255] ""  PC
 SG_ S2P_Response_Byte4_56 : 24|8@1+ (1,0) [0|255] ""  PC
 SG_ S2P_Response_Byte5_56 : 32|8@1+ (1,0) [0|255] ""  PC
 SG_ S2P_Response_Byte6_56 : 40|8@1+ (1,0) [0|255] ""  PC
 SG_ S2P_Response_Byte7_56 : 48|8@1+ (1,0) [0|255] ""  PC
 SG_ S2P_Response_Byte8_56 : 56|8@1+ (1,0) [0|255] ""  PC

BO_ 2417880697 S2P_Response__57: 8 SBMU
 SG_ S2P_Response_Byte1_57 : 0|8@1+ (1,0) [0|255] ""  PC
 SG_ S2P_Response_Byte2_57 : 8|8@1+ (1,0) [0|255] ""  PC
 SG_ S2P_Response_Byte3_57 : 16|8@1+ (1,0) [0|255] ""  PC
 SG_ S2P_Response_Byte4_57 : 24|8@1+ (1,0) [0|255] ""  PC
 SG_ S2P_Response_Byte5_57 : 32|8@1+ (1,0) [0|255] ""  PC
 SG_ S2P_Response_Byte6_57 : 40|8@1+ (1,0) [0|255] ""  PC
 SG_ S2P_Response_Byte7_57 : 48|8@1+ (1,0) [0|255] ""  PC
 SG_ S2P_Response_Byte8_57 : 56|8@1+ (1,0) [0|255] ""  PC

BO_ 2417880698 S2P_Response__58: 8 SBMU
 SG_ S2P_Response_Byte1_58 : 0|8@1+ (1,0) [0|255] ""  PC
 SG_ S2P_Response_Byte2_58 : 8|8@1+ (1,0) [0|255] ""  PC
 SG_ S2P_Response_Byte3_58 : 16|8@1+ (1,0) [0|255] ""  PC
 SG_ S2P_Response_Byte4_58 : 24|8@1+ (1,0) [0|255] ""  PC
 SG_ S2P_Response_Byte5_58 : 32|8@1+ (1,0) [0|255] ""  PC
 SG_ S2P_Response_Byte6_58 : 40|8@1+ (1,0) [0|255] ""  PC
 SG_ S2P_Response_Byte7_58 : 48|8@1+ (1,0) [0|255] ""  PC
 SG_ S2P_Response_Byte8_58 : 56|8@1+ (1,0) [0|255] ""  PC

BO_ 2417880699 S2P_Response__59: 8 SBMU
 SG_ S2P_Response_Byte1_59 : 0|8@1+ (1,0) [0|255] ""  PC
 SG_ S2P_Response_Byte2_59 : 8|8@1+ (1,0) [0|255] ""  PC
 SG_ S2P_Response_Byte3_59 : 16|8@1+ (1,0) [0|255] ""  PC
 SG_ S2P_Response_Byte4_59 : 24|8@1+ (1,0) [0|255] ""  PC
 SG_ S2P_Response_Byte5_59 : 32|8@1+ (1,0) [0|255] ""  PC
 SG_ S2P_Response_Byte6_59 : 40|8@1+ (1,0) [0|255] ""  PC
 SG_ S2P_Response_Byte7_59 : 48|8@1+ (1,0) [0|255] ""  PC
 SG_ S2P_Response_Byte8_59 : 56|8@1+ (1,0) [0|255] ""  PC

BO_ 2417880700 S2P_Response__60: 8 SBMU
 SG_ S2P_Response_Byte1_60 : 0|8@1+ (1,0) [0|255] ""  PC
 SG_ S2P_Response_Byte2_60 : 8|8@1+ (1,0) [0|255] ""  PC
 SG_ S2P_Response_Byte3_60 : 16|8@1+ (1,0) [0|255] ""  PC
 SG_ S2P_Response_Byte4_60 : 24|8@1+ (1,0) [0|255] ""  PC
 SG_ S2P_Response_Byte5_60 : 32|8@1+ (1,0) [0|255] ""  PC
 SG_ S2P_Response_Byte6_60 : 40|8@1+ (1,0) [0|255] ""  PC
 SG_ S2P_Response_Byte7_60 : 48|8@1+ (1,0) [0|255] ""  PC
 SG_ S2P_Response_Byte8_60 : 56|8@1+ (1,0) [0|255] ""  PC

BO_ 2417880701 S2P_Response__61: 8 SBMU
 SG_ S2P_Response_Byte1_61 : 0|8@1+ (1,0) [0|255] ""  PC
 SG_ S2P_Response_Byte2_61 : 8|8@1+ (1,0) [0|255] ""  PC
 SG_ S2P_Response_Byte3_61 : 16|8@1+ (1,0) [0|255] ""  PC
 SG_ S2P_Response_Byte4_61 : 24|8@1+ (1,0) [0|255] ""  PC
 SG_ S2P_Response_Byte5_61 : 32|8@1+ (1,0) [0|255] ""  PC
 SG_ S2P_Response_Byte6_61 : 40|8@1+ (1,0) [0|255] ""  PC
 SG_ S2P_Response_Byte7_61 : 48|8@1+ (1,0) [0|255] ""  PC
 SG_ S2P_Response_Byte8_61 : 56|8@1+ (1,0) [0|255] ""  PC

BO_ 2417880702 S2P_Response__62: 8 SBMU
 SG_ S2P_Response_Byte1_62 : 0|8@1+ (1,0) [0|255] ""  PC
 SG_ S2P_Response_Byte2_62 : 8|8@1+ (1,0) [0|255] ""  PC
 SG_ S2P_Response_Byte3_62 : 16|8@1+ (1,0) [0|255] ""  PC
 SG_ S2P_Response_Byte4_62 : 24|8@1+ (1,0) [0|255] ""  PC
 SG_ S2P_Response_Byte5_62 : 32|8@1+ (1,0) [0|255] ""  PC
 SG_ S2P_Response_Byte6_62 : 40|8@1+ (1,0) [0|255] ""  PC
 SG_ S2P_Response_Byte7_62 : 48|8@1+ (1,0) [0|255] ""  PC
 SG_ S2P_Response_Byte8_62 : 56|8@1+ (1,0) [0|255] ""  PC

BO_ 2417880703 S2P_Response__63: 8 SBMU
 SG_ S2P_Response_Byte1_63 : 0|8@1+ (1,0) [0|255] ""  PC
 SG_ S2P_Response_Byte2_63 : 8|8@1+ (1,0) [0|255] ""  PC
 SG_ S2P_Response_Byte3_63 : 16|8@1+ (1,0) [0|255] ""  PC
 SG_ S2P_Response_Byte4_63 : 24|8@1+ (1,0) [0|255] ""  PC
 SG_ S2P_Response_Byte5_63 : 32|8@1+ (1,0) [0|255] ""  PC
 SG_ S2P_Response_Byte6_63 : 40|8@1+ (1,0) [0|255] ""  PC
 SG_ S2P_Response_Byte7_63 : 48|8@1+ (1,0) [0|255] ""  PC
 SG_ S2P_Response_Byte8_63 : 56|8@1+ (1,0) [0|255] ""  PC

BO_ 2418601537 S2P_Cfg12__01: 8 SBMU
 SG_ S2P_Cfg12_SW_Ver_Byte1_01 : 0|8@1+ (1,0) [0|255] ""  PC
 SG_ S2P_Cfg12_SW_Ver_Byte2_01 : 8|8@1+ (1,0) [0|255] ""  PC
 SG_ S2P_Cfg12_SW_Ver_Byte3_01 : 16|8@1+ (1,0) [0|255] ""  PC
 SG_ S2P_Cfg12_SW_Ver_Byte4_01 : 24|8@1+ (1,0) [0|255] ""  PC
 SG_ S2P_Cfg12_SW_Ver_Byte5_01 : 32|8@1+ (1,0) [0|255] ""  PC
 SG_ S2P_Cfg12_SW_Ver_Byte6_01 : 40|8@1+ (1,0) [0|255] ""  PC
 SG_ S2P_Cfg12_SW_Ver_Byte7_01 : 48|8@1+ (1,0) [0|255] ""  PC
 SG_ S2P_Cfg12_SW_Ver_Byte8_01 : 56|8@1+ (1,0) [0|255] ""  PC

BO_ 2418601538 S2P_Cfg12__02: 8 SBMU
 SG_ S2P_Cfg12_SW_Ver_Byte1_02 : 0|8@1+ (1,0) [0|255] ""  PC
 SG_ S2P_Cfg12_SW_Ver_Byte2_02 : 8|8@1+ (1,0) [0|255] ""  PC
 SG_ S2P_Cfg12_SW_Ver_Byte3_02 : 16|8@1+ (1,0) [0|255] ""  PC
 SG_ S2P_Cfg12_SW_Ver_Byte4_02 : 24|8@1+ (1,0) [0|255] ""  PC
 SG_ S2P_Cfg12_SW_Ver_Byte5_02 : 32|8@1+ (1,0) [0|255] ""  PC
 SG_ S2P_Cfg12_SW_Ver_Byte6_02 : 40|8@1+ (1,0) [0|255] ""  PC
 SG_ S2P_Cfg12_SW_Ver_Byte7_02 : 48|8@1+ (1,0) [0|255] ""  PC
 SG_ S2P_Cfg12_SW_Ver_Byte8_02 : 56|8@1+ (1,0) [0|255] ""  PC

BO_ 2418601539 S2P_Cfg12__03: 8 SBMU
 SG_ S2P_Cfg12_SW_Ver_Byte1_03 : 0|8@1+ (1,0) [0|255] ""  PC
 SG_ S2P_Cfg12_SW_Ver_Byte2_03 : 8|8@1+ (1,0) [0|255] ""  PC
 SG_ S2P_Cfg12_SW_Ver_Byte3_03 : 16|8@1+ (1,0) [0|255] ""  PC
 SG_ S2P_Cfg12_SW_Ver_Byte4_03 : 24|8@1+ (1,0) [0|255] ""  PC
 SG_ S2P_Cfg12_SW_Ver_Byte5_03 : 32|8@1+ (1,0) [0|255] ""  PC
 SG_ S2P_Cfg12_SW_Ver_Byte6_03 : 40|8@1+ (1,0) [0|255] ""  PC
 SG_ S2P_Cfg12_SW_Ver_Byte7_03 : 48|8@1+ (1,0) [0|255] ""  PC
 SG_ S2P_Cfg12_SW_Ver_Byte8_03 : 56|8@1+ (1,0) [0|255] ""  PC

BO_ 2418601540 S2P_Cfg12__04: 8 SBMU
 SG_ S2P_Cfg12_SW_Ver_Byte1_04 : 0|8@1+ (1,0) [0|255] ""  PC
 SG_ S2P_Cfg12_SW_Ver_Byte2_04 : 8|8@1+ (1,0) [0|255] ""  PC
 SG_ S2P_Cfg12_SW_Ver_Byte3_04 : 16|8@1+ (1,0) [0|255] ""  PC
 SG_ S2P_Cfg12_SW_Ver_Byte4_04 : 24|8@1+ (1,0) [0|255] ""  PC
 SG_ S2P_Cfg12_SW_Ver_Byte5_04 : 32|8@1+ (1,0) [0|255] ""  PC
 SG_ S2P_Cfg12_SW_Ver_Byte6_04 : 40|8@1+ (1,0) [0|255] ""  PC
 SG_ S2P_Cfg12_SW_Ver_Byte7_04 : 48|8@1+ (1,0) [0|255] ""  PC
 SG_ S2P_Cfg12_SW_Ver_Byte8_04 : 56|8@1+ (1,0) [0|255] ""  PC

BO_ 2418601541 S2P_Cfg12__05: 8 SBMU
 SG_ S2P_Cfg12_SW_Ver_Byte1_05 : 0|8@1+ (1,0) [0|255] ""  PC
 SG_ S2P_Cfg12_SW_Ver_Byte2_05 : 8|8@1+ (1,0) [0|255] ""  PC
 SG_ S2P_Cfg12_SW_Ver_Byte3_05 : 16|8@1+ (1,0) [0|255] ""  PC
 SG_ S2P_Cfg12_SW_Ver_Byte4_05 : 24|8@1+ (1,0) [0|255] ""  PC
 SG_ S2P_Cfg12_SW_Ver_Byte5_05 : 32|8@1+ (1,0) [0|255] ""  PC
 SG_ S2P_Cfg12_SW_Ver_Byte6_05 : 40|8@1+ (1,0) [0|255] ""  PC
 SG_ S2P_Cfg12_SW_Ver_Byte7_05 : 48|8@1+ (1,0) [0|255] ""  PC
 SG_ S2P_Cfg12_SW_Ver_Byte8_05 : 56|8@1+ (1,0) [0|255] ""  PC

BO_ 2418601542 S2P_Cfg12__06: 8 SBMU
 SG_ S2P_Cfg12_SW_Ver_Byte1_06 : 0|8@1+ (1,0) [0|255] ""  PC
 SG_ S2P_Cfg12_SW_Ver_Byte2_06 : 8|8@1+ (1,0) [0|255] ""  PC
 SG_ S2P_Cfg12_SW_Ver_Byte3_06 : 16|8@1+ (1,0) [0|255] ""  PC
 SG_ S2P_Cfg12_SW_Ver_Byte4_06 : 24|8@1+ (1,0) [0|255] ""  PC
 SG_ S2P_Cfg12_SW_Ver_Byte5_06 : 32|8@1+ (1,0) [0|255] ""  PC
 SG_ S2P_Cfg12_SW_Ver_Byte6_06 : 40|8@1+ (1,0) [0|255] ""  PC
 SG_ S2P_Cfg12_SW_Ver_Byte7_06 : 48|8@1+ (1,0) [0|255] ""  PC
 SG_ S2P_Cfg12_SW_Ver_Byte8_06 : 56|8@1+ (1,0) [0|255] ""  PC

BO_ 2418601543 S2P_Cfg12__07: 8 SBMU
 SG_ S2P_Cfg12_SW_Ver_Byte1_07 : 0|8@1+ (1,0) [0|255] ""  PC
 SG_ S2P_Cfg12_SW_Ver_Byte2_07 : 8|8@1+ (1,0) [0|255] ""  PC
 SG_ S2P_Cfg12_SW_Ver_Byte3_07 : 16|8@1+ (1,0) [0|255] ""  PC
 SG_ S2P_Cfg12_SW_Ver_Byte4_07 : 24|8@1+ (1,0) [0|255] ""  PC
 SG_ S2P_Cfg12_SW_Ver_Byte5_07 : 32|8@1+ (1,0) [0|255] ""  PC
 SG_ S2P_Cfg12_SW_Ver_Byte6_07 : 40|8@1+ (1,0) [0|255] ""  PC
 SG_ S2P_Cfg12_SW_Ver_Byte7_07 : 48|8@1+ (1,0) [0|255] ""  PC
 SG_ S2P_Cfg12_SW_Ver_Byte8_07 : 56|8@1+ (1,0) [0|255] ""  PC

BO_ 2418601544 S2P_Cfg12__08: 8 SBMU
 SG_ S2P_Cfg12_SW_Ver_Byte1_08 : 0|8@1+ (1,0) [0|255] ""  PC
 SG_ S2P_Cfg12_SW_Ver_Byte2_08 : 8|8@1+ (1,0) [0|255] ""  PC
 SG_ S2P_Cfg12_SW_Ver_Byte3_08 : 16|8@1+ (1,0) [0|255] ""  PC
 SG_ S2P_Cfg12_SW_Ver_Byte4_08 : 24|8@1+ (1,0) [0|255] ""  PC
 SG_ S2P_Cfg12_SW_Ver_Byte5_08 : 32|8@1+ (1,0) [0|255] ""  PC
 SG_ S2P_Cfg12_SW_Ver_Byte6_08 : 40|8@1+ (1,0) [0|255] ""  PC
 SG_ S2P_Cfg12_SW_Ver_Byte7_08 : 48|8@1+ (1,0) [0|255] ""  PC
 SG_ S2P_Cfg12_SW_Ver_Byte8_08 : 56|8@1+ (1,0) [0|255] ""  PC

BO_ 2418601545 S2P_Cfg12__09: 8 SBMU
 SG_ S2P_Cfg12_SW_Ver_Byte1_09 : 0|8@1+ (1,0) [0|255] ""  PC
 SG_ S2P_Cfg12_SW_Ver_Byte2_09 : 8|8@1+ (1,0) [0|255] ""  PC
 SG_ S2P_Cfg12_SW_Ver_Byte3_09 : 16|8@1+ (1,0) [0|255] ""  PC
 SG_ S2P_Cfg12_SW_Ver_Byte4_09 : 24|8@1+ (1,0) [0|255] ""  PC
 SG_ S2P_Cfg12_SW_Ver_Byte5_09 : 32|8@1+ (1,0) [0|255] ""  PC
 SG_ S2P_Cfg12_SW_Ver_Byte6_09 : 40|8@1+ (1,0) [0|255] ""  PC
 SG_ S2P_Cfg12_SW_Ver_Byte7_09 : 48|8@1+ (1,0) [0|255] ""  PC
 SG_ S2P_Cfg12_SW_Ver_Byte8_09 : 56|8@1+ (1,0) [0|255] ""  PC

BO_ 2418601546 S2P_Cfg12__10: 8 SBMU
 SG_ S2P_Cfg12_SW_Ver_Byte1_10 : 0|8@1+ (1,0) [0|255] ""  PC
 SG_ S2P_Cfg12_SW_Ver_Byte2_10 : 8|8@1+ (1,0) [0|255] ""  PC
 SG_ S2P_Cfg12_SW_Ver_Byte3_10 : 16|8@1+ (1,0) [0|255] ""  PC
 SG_ S2P_Cfg12_SW_Ver_Byte4_10 : 24|8@1+ (1,0) [0|255] ""  PC
 SG_ S2P_Cfg12_SW_Ver_Byte5_10 : 32|8@1+ (1,0) [0|255] ""  PC
 SG_ S2P_Cfg12_SW_Ver_Byte6_10 : 40|8@1+ (1,0) [0|255] ""  PC
 SG_ S2P_Cfg12_SW_Ver_Byte7_10 : 48|8@1+ (1,0) [0|255] ""  PC
 SG_ S2P_Cfg12_SW_Ver_Byte8_10 : 56|8@1+ (1,0) [0|255] ""  PC

BO_ 2418601547 S2P_Cfg12__11: 8 SBMU
 SG_ S2P_Cfg12_SW_Ver_Byte1_11 : 0|8@1+ (1,0) [0|255] ""  PC
 SG_ S2P_Cfg12_SW_Ver_Byte2_11 : 8|8@1+ (1,0) [0|255] ""  PC
 SG_ S2P_Cfg12_SW_Ver_Byte3_11 : 16|8@1+ (1,0) [0|255] ""  PC
 SG_ S2P_Cfg12_SW_Ver_Byte4_11 : 24|8@1+ (1,0) [0|255] ""  PC
 SG_ S2P_Cfg12_SW_Ver_Byte5_11 : 32|8@1+ (1,0) [0|255] ""  PC
 SG_ S2P_Cfg12_SW_Ver_Byte6_11 : 40|8@1+ (1,0) [0|255] ""  PC
 SG_ S2P_Cfg12_SW_Ver_Byte7_11 : 48|8@1+ (1,0) [0|255] ""  PC
 SG_ S2P_Cfg12_SW_Ver_Byte8_11 : 56|8@1+ (1,0) [0|255] ""  PC

BO_ 2418601548 S2P_Cfg12__12: 8 SBMU
 SG_ S2P_Cfg12_SW_Ver_Byte1_12 : 0|8@1+ (1,0) [0|255] ""  PC
 SG_ S2P_Cfg12_SW_Ver_Byte2_12 : 8|8@1+ (1,0) [0|255] ""  PC
 SG_ S2P_Cfg12_SW_Ver_Byte3_12 : 16|8@1+ (1,0) [0|255] ""  PC
 SG_ S2P_Cfg12_SW_Ver_Byte4_12 : 24|8@1+ (1,0) [0|255] ""  PC
 SG_ S2P_Cfg12_SW_Ver_Byte5_12 : 32|8@1+ (1,0) [0|255] ""  PC
 SG_ S2P_Cfg12_SW_Ver_Byte6_12 : 40|8@1+ (1,0) [0|255] ""  PC
 SG_ S2P_Cfg12_SW_Ver_Byte7_12 : 48|8@1+ (1,0) [0|255] ""  PC
 SG_ S2P_Cfg12_SW_Ver_Byte8_12 : 56|8@1+ (1,0) [0|255] ""  PC

BO_ 2418601549 S2P_Cfg12__13: 8 SBMU
 SG_ S2P_Cfg12_SW_Ver_Byte1_13 : 0|8@1+ (1,0) [0|255] ""  PC
 SG_ S2P_Cfg12_SW_Ver_Byte2_13 : 8|8@1+ (1,0) [0|255] ""  PC
 SG_ S2P_Cfg12_SW_Ver_Byte3_13 : 16|8@1+ (1,0) [0|255] ""  PC
 SG_ S2P_Cfg12_SW_Ver_Byte4_13 : 24|8@1+ (1,0) [0|255] ""  PC
 SG_ S2P_Cfg12_SW_Ver_Byte5_13 : 32|8@1+ (1,0) [0|255] ""  PC
 SG_ S2P_Cfg12_SW_Ver_Byte6_13 : 40|8@1+ (1,0) [0|255] ""  PC
 SG_ S2P_Cfg12_SW_Ver_Byte7_13 : 48|8@1+ (1,0) [0|255] ""  PC
 SG_ S2P_Cfg12_SW_Ver_Byte8_13 : 56|8@1+ (1,0) [0|255] ""  PC

BO_ 2418601550 S2P_Cfg12__14: 8 SBMU
 SG_ S2P_Cfg12_SW_Ver_Byte1_14 : 0|8@1+ (1,0) [0|255] ""  PC
 SG_ S2P_Cfg12_SW_Ver_Byte2_14 : 8|8@1+ (1,0) [0|255] ""  PC
 SG_ S2P_Cfg12_SW_Ver_Byte3_14 : 16|8@1+ (1,0) [0|255] ""  PC
 SG_ S2P_Cfg12_SW_Ver_Byte4_14 : 24|8@1+ (1,0) [0|255] ""  PC
 SG_ S2P_Cfg12_SW_Ver_Byte5_14 : 32|8@1+ (1,0) [0|255] ""  PC
 SG_ S2P_Cfg12_SW_Ver_Byte6_14 : 40|8@1+ (1,0) [0|255] ""  PC
 SG_ S2P_Cfg12_SW_Ver_Byte7_14 : 48|8@1+ (1,0) [0|255] ""  PC
 SG_ S2P_Cfg12_SW_Ver_Byte8_14 : 56|8@1+ (1,0) [0|255] ""  PC

BO_ 2418601551 S2P_Cfg12__15: 8 SBMU
 SG_ S2P_Cfg12_SW_Ver_Byte1_15 : 0|8@1+ (1,0) [0|255] ""  PC
 SG_ S2P_Cfg12_SW_Ver_Byte2_15 : 8|8@1+ (1,0) [0|255] ""  PC
 SG_ S2P_Cfg12_SW_Ver_Byte3_15 : 16|8@1+ (1,0) [0|255] ""  PC
 SG_ S2P_Cfg12_SW_Ver_Byte4_15 : 24|8@1+ (1,0) [0|255] ""  PC
 SG_ S2P_Cfg12_SW_Ver_Byte5_15 : 32|8@1+ (1,0) [0|255] ""  PC
 SG_ S2P_Cfg12_SW_Ver_Byte6_15 : 40|8@1+ (1,0) [0|255] ""  PC
 SG_ S2P_Cfg12_SW_Ver_Byte7_15 : 48|8@1+ (1,0) [0|255] ""  PC
 SG_ S2P_Cfg12_SW_Ver_Byte8_15 : 56|8@1+ (1,0) [0|255] ""  PC

BO_ 2418601552 S2P_Cfg12__16: 8 SBMU
 SG_ S2P_Cfg12_SW_Ver_Byte1_16 : 0|8@1+ (1,0) [0|255] ""  PC
 SG_ S2P_Cfg12_SW_Ver_Byte2_16 : 8|8@1+ (1,0) [0|255] ""  PC
 SG_ S2P_Cfg12_SW_Ver_Byte3_16 : 16|8@1+ (1,0) [0|255] ""  PC
 SG_ S2P_Cfg12_SW_Ver_Byte4_16 : 24|8@1+ (1,0) [0|255] ""  PC
 SG_ S2P_Cfg12_SW_Ver_Byte5_16 : 32|8@1+ (1,0) [0|255] ""  PC
 SG_ S2P_Cfg12_SW_Ver_Byte6_16 : 40|8@1+ (1,0) [0|255] ""  PC
 SG_ S2P_Cfg12_SW_Ver_Byte7_16 : 48|8@1+ (1,0) [0|255] ""  PC
 SG_ S2P_Cfg12_SW_Ver_Byte8_16 : 56|8@1+ (1,0) [0|255] ""  PC

BO_ 2418601553 S2P_Cfg12__17: 8 SBMU
 SG_ S2P_Cfg12_SW_Ver_Byte1_17 : 0|8@1+ (1,0) [0|255] ""  PC
 SG_ S2P_Cfg12_SW_Ver_Byte2_17 : 8|8@1+ (1,0) [0|255] ""  PC
 SG_ S2P_Cfg12_SW_Ver_Byte3_17 : 16|8@1+ (1,0) [0|255] ""  PC
 SG_ S2P_Cfg12_SW_Ver_Byte4_17 : 24|8@1+ (1,0) [0|255] ""  PC
 SG_ S2P_Cfg12_SW_Ver_Byte5_17 : 32|8@1+ (1,0) [0|255] ""  PC
 SG_ S2P_Cfg12_SW_Ver_Byte6_17 : 40|8@1+ (1,0) [0|255] ""  PC
 SG_ S2P_Cfg12_SW_Ver_Byte7_17 : 48|8@1+ (1,0) [0|255] ""  PC
 SG_ S2P_Cfg12_SW_Ver_Byte8_17 : 56|8@1+ (1,0) [0|255] ""  PC

BO_ 2418601554 S2P_Cfg12__18: 8 SBMU
 SG_ S2P_Cfg12_SW_Ver_Byte1_18 : 0|8@1+ (1,0) [0|255] ""  PC
 SG_ S2P_Cfg12_SW_Ver_Byte2_18 : 8|8@1+ (1,0) [0|255] ""  PC
 SG_ S2P_Cfg12_SW_Ver_Byte3_18 : 16|8@1+ (1,0) [0|255] ""  PC
 SG_ S2P_Cfg12_SW_Ver_Byte4_18 : 24|8@1+ (1,0) [0|255] ""  PC
 SG_ S2P_Cfg12_SW_Ver_Byte5_18 : 32|8@1+ (1,0) [0|255] ""  PC
 SG_ S2P_Cfg12_SW_Ver_Byte6_18 : 40|8@1+ (1,0) [0|255] ""  PC
 SG_ S2P_Cfg12_SW_Ver_Byte7_18 : 48|8@1+ (1,0) [0|255] ""  PC
 SG_ S2P_Cfg12_SW_Ver_Byte8_18 : 56|8@1+ (1,0) [0|255] ""  PC

BO_ 2418601555 S2P_Cfg12__19: 8 SBMU
 SG_ S2P_Cfg12_SW_Ver_Byte1_19 : 0|8@1+ (1,0) [0|255] ""  PC
 SG_ S2P_Cfg12_SW_Ver_Byte2_19 : 8|8@1+ (1,0) [0|255] ""  PC
 SG_ S2P_Cfg12_SW_Ver_Byte3_19 : 16|8@1+ (1,0) [0|255] ""  PC
 SG_ S2P_Cfg12_SW_Ver_Byte4_19 : 24|8@1+ (1,0) [0|255] ""  PC
 SG_ S2P_Cfg12_SW_Ver_Byte5_19 : 32|8@1+ (1,0) [0|255] ""  PC
 SG_ S2P_Cfg12_SW_Ver_Byte6_19 : 40|8@1+ (1,0) [0|255] ""  PC
 SG_ S2P_Cfg12_SW_Ver_Byte7_19 : 48|8@1+ (1,0) [0|255] ""  PC
 SG_ S2P_Cfg12_SW_Ver_Byte8_19 : 56|8@1+ (1,0) [0|255] ""  PC

BO_ 2418601556 S2P_Cfg12__20: 8 SBMU
 SG_ S2P_Cfg12_SW_Ver_Byte1_20 : 0|8@1+ (1,0) [0|255] ""  PC
 SG_ S2P_Cfg12_SW_Ver_Byte2_20 : 8|8@1+ (1,0) [0|255] ""  PC
 SG_ S2P_Cfg12_SW_Ver_Byte3_20 : 16|8@1+ (1,0) [0|255] ""  PC
 SG_ S2P_Cfg12_SW_Ver_Byte4_20 : 24|8@1+ (1,0) [0|255] ""  PC
 SG_ S2P_Cfg12_SW_Ver_Byte5_20 : 32|8@1+ (1,0) [0|255] ""  PC
 SG_ S2P_Cfg12_SW_Ver_Byte6_20 : 40|8@1+ (1,0) [0|255] ""  PC
 SG_ S2P_Cfg12_SW_Ver_Byte7_20 : 48|8@1+ (1,0) [0|255] ""  PC
 SG_ S2P_Cfg12_SW_Ver_Byte8_20 : 56|8@1+ (1,0) [0|255] ""  PC

BO_ 2418601557 S2P_Cfg12__21: 8 SBMU
 SG_ S2P_Cfg12_SW_Ver_Byte1_21 : 0|8@1+ (1,0) [0|255] ""  PC
 SG_ S2P_Cfg12_SW_Ver_Byte2_21 : 8|8@1+ (1,0) [0|255] ""  PC
 SG_ S2P_Cfg12_SW_Ver_Byte3_21 : 16|8@1+ (1,0) [0|255] ""  PC
 SG_ S2P_Cfg12_SW_Ver_Byte4_21 : 24|8@1+ (1,0) [0|255] ""  PC
 SG_ S2P_Cfg12_SW_Ver_Byte5_21 : 32|8@1+ (1,0) [0|255] ""  PC
 SG_ S2P_Cfg12_SW_Ver_Byte6_21 : 40|8@1+ (1,0) [0|255] ""  PC
 SG_ S2P_Cfg12_SW_Ver_Byte7_21 : 48|8@1+ (1,0) [0|255] ""  PC
 SG_ S2P_Cfg12_SW_Ver_Byte8_21 : 56|8@1+ (1,0) [0|255] ""  PC

BO_ 2418601558 S2P_Cfg12__22: 8 SBMU
 SG_ S2P_Cfg12_SW_Ver_Byte1_22 : 0|8@1+ (1,0) [0|255] ""  PC
 SG_ S2P_Cfg12_SW_Ver_Byte2_22 : 8|8@1+ (1,0) [0|255] ""  PC
 SG_ S2P_Cfg12_SW_Ver_Byte3_22 : 16|8@1+ (1,0) [0|255] ""  PC
 SG_ S2P_Cfg12_SW_Ver_Byte4_22 : 24|8@1+ (1,0) [0|255] ""  PC
 SG_ S2P_Cfg12_SW_Ver_Byte5_22 : 32|8@1+ (1,0) [0|255] ""  PC
 SG_ S2P_Cfg12_SW_Ver_Byte6_22 : 40|8@1+ (1,0) [0|255] ""  PC
 SG_ S2P_Cfg12_SW_Ver_Byte7_22 : 48|8@1+ (1,0) [0|255] ""  PC
 SG_ S2P_Cfg12_SW_Ver_Byte8_22 : 56|8@1+ (1,0) [0|255] ""  PC

BO_ 2418601559 S2P_Cfg12__23: 8 SBMU
 SG_ S2P_Cfg12_SW_Ver_Byte1_23 : 0|8@1+ (1,0) [0|255] ""  PC
 SG_ S2P_Cfg12_SW_Ver_Byte2_23 : 8|8@1+ (1,0) [0|255] ""  PC
 SG_ S2P_Cfg12_SW_Ver_Byte3_23 : 16|8@1+ (1,0) [0|255] ""  PC
 SG_ S2P_Cfg12_SW_Ver_Byte4_23 : 24|8@1+ (1,0) [0|255] ""  PC
 SG_ S2P_Cfg12_SW_Ver_Byte5_23 : 32|8@1+ (1,0) [0|255] ""  PC
 SG_ S2P_Cfg12_SW_Ver_Byte6_23 : 40|8@1+ (1,0) [0|255] ""  PC
 SG_ S2P_Cfg12_SW_Ver_Byte7_23 : 48|8@1+ (1,0) [0|255] ""  PC
 SG_ S2P_Cfg12_SW_Ver_Byte8_23 : 56|8@1+ (1,0) [0|255] ""  PC

BO_ 2418601560 S2P_Cfg12__24: 8 SBMU
 SG_ S2P_Cfg12_SW_Ver_Byte1_24 : 0|8@1+ (1,0) [0|255] ""  PC
 SG_ S2P_Cfg12_SW_Ver_Byte2_24 : 8|8@1+ (1,0) [0|255] ""  PC
 SG_ S2P_Cfg12_SW_Ver_Byte3_24 : 16|8@1+ (1,0) [0|255] ""  PC
 SG_ S2P_Cfg12_SW_Ver_Byte4_24 : 24|8@1+ (1,0) [0|255] ""  PC
 SG_ S2P_Cfg12_SW_Ver_Byte5_24 : 32|8@1+ (1,0) [0|255] ""  PC
 SG_ S2P_Cfg12_SW_Ver_Byte6_24 : 40|8@1+ (1,0) [0|255] ""  PC
 SG_ S2P_Cfg12_SW_Ver_Byte7_24 : 48|8@1+ (1,0) [0|255] ""  PC
 SG_ S2P_Cfg12_SW_Ver_Byte8_24 : 56|8@1+ (1,0) [0|255] ""  PC

BO_ 2418601561 S2P_Cfg12__25: 8 SBMU
 SG_ S2P_Cfg12_SW_Ver_Byte1_25 : 0|8@1+ (1,0) [0|255] ""  PC
 SG_ S2P_Cfg12_SW_Ver_Byte2_25 : 8|8@1+ (1,0) [0|255] ""  PC
 SG_ S2P_Cfg12_SW_Ver_Byte3_25 : 16|8@1+ (1,0) [0|255] ""  PC
 SG_ S2P_Cfg12_SW_Ver_Byte4_25 : 24|8@1+ (1,0) [0|255] ""  PC
 SG_ S2P_Cfg12_SW_Ver_Byte5_25 : 32|8@1+ (1,0) [0|255] ""  PC
 SG_ S2P_Cfg12_SW_Ver_Byte6_25 : 40|8@1+ (1,0) [0|255] ""  PC
 SG_ S2P_Cfg12_SW_Ver_Byte7_25 : 48|8@1+ (1,0) [0|255] ""  PC
 SG_ S2P_Cfg12_SW_Ver_Byte8_25 : 56|8@1+ (1,0) [0|255] ""  PC

BO_ 2418601562 S2P_Cfg12__26: 8 SBMU
 SG_ S2P_Cfg12_SW_Ver_Byte1_26 : 0|8@1+ (1,0) [0|255] ""  PC
 SG_ S2P_Cfg12_SW_Ver_Byte2_26 : 8|8@1+ (1,0) [0|255] ""  PC
 SG_ S2P_Cfg12_SW_Ver_Byte3_26 : 16|8@1+ (1,0) [0|255] ""  PC
 SG_ S2P_Cfg12_SW_Ver_Byte4_26 : 24|8@1+ (1,0) [0|255] ""  PC
 SG_ S2P_Cfg12_SW_Ver_Byte5_26 : 32|8@1+ (1,0) [0|255] ""  PC
 SG_ S2P_Cfg12_SW_Ver_Byte6_26 : 40|8@1+ (1,0) [0|255] ""  PC
 SG_ S2P_Cfg12_SW_Ver_Byte7_26 : 48|8@1+ (1,0) [0|255] ""  PC
 SG_ S2P_Cfg12_SW_Ver_Byte8_26 : 56|8@1+ (1,0) [0|255] ""  PC

BO_ 2418601563 S2P_Cfg12__27: 8 SBMU
 SG_ S2P_Cfg12_SW_Ver_Byte1_27 : 0|8@1+ (1,0) [0|255] ""  PC
 SG_ S2P_Cfg12_SW_Ver_Byte2_27 : 8|8@1+ (1,0) [0|255] ""  PC
 SG_ S2P_Cfg12_SW_Ver_Byte3_27 : 16|8@1+ (1,0) [0|255] ""  PC
 SG_ S2P_Cfg12_SW_Ver_Byte4_27 : 24|8@1+ (1,0) [0|255] ""  PC
 SG_ S2P_Cfg12_SW_Ver_Byte5_27 : 32|8@1+ (1,0) [0|255] ""  PC
 SG_ S2P_Cfg12_SW_Ver_Byte6_27 : 40|8@1+ (1,0) [0|255] ""  PC
 SG_ S2P_Cfg12_SW_Ver_Byte7_27 : 48|8@1+ (1,0) [0|255] ""  PC
 SG_ S2P_Cfg12_SW_Ver_Byte8_27 : 56|8@1+ (1,0) [0|255] ""  PC

BO_ 2418601564 S2P_Cfg12__28: 8 SBMU
 SG_ S2P_Cfg12_SW_Ver_Byte1_28 : 0|8@1+ (1,0) [0|255] ""  PC
 SG_ S2P_Cfg12_SW_Ver_Byte2_28 : 8|8@1+ (1,0) [0|255] ""  PC
 SG_ S2P_Cfg12_SW_Ver_Byte3_28 : 16|8@1+ (1,0) [0|255] ""  PC
 SG_ S2P_Cfg12_SW_Ver_Byte4_28 : 24|8@1+ (1,0) [0|255] ""  PC
 SG_ S2P_Cfg12_SW_Ver_Byte5_28 : 32|8@1+ (1,0) [0|255] ""  PC
 SG_ S2P_Cfg12_SW_Ver_Byte6_28 : 40|8@1+ (1,0) [0|255] ""  PC
 SG_ S2P_Cfg12_SW_Ver_Byte7_28 : 48|8@1+ (1,0) [0|255] ""  PC
 SG_ S2P_Cfg12_SW_Ver_Byte8_28 : 56|8@1+ (1,0) [0|255] ""  PC

BO_ 2418601565 S2P_Cfg12__29: 8 SBMU
 SG_ S2P_Cfg12_SW_Ver_Byte1_29 : 0|8@1+ (1,0) [0|255] ""  PC
 SG_ S2P_Cfg12_SW_Ver_Byte2_29 : 8|8@1+ (1,0) [0|255] ""  PC
 SG_ S2P_Cfg12_SW_Ver_Byte3_29 : 16|8@1+ (1,0) [0|255] ""  PC
 SG_ S2P_Cfg12_SW_Ver_Byte4_29 : 24|8@1+ (1,0) [0|255] ""  PC
 SG_ S2P_Cfg12_SW_Ver_Byte5_29 : 32|8@1+ (1,0) [0|255] ""  PC
 SG_ S2P_Cfg12_SW_Ver_Byte6_29 : 40|8@1+ (1,0) [0|255] ""  PC
 SG_ S2P_Cfg12_SW_Ver_Byte7_29 : 48|8@1+ (1,0) [0|255] ""  PC
 SG_ S2P_Cfg12_SW_Ver_Byte8_29 : 56|8@1+ (1,0) [0|255] ""  PC

BO_ 2418601566 S2P_Cfg12__30: 8 SBMU
 SG_ S2P_Cfg12_SW_Ver_Byte1_30 : 0|8@1+ (1,0) [0|255] ""  PC
 SG_ S2P_Cfg12_SW_Ver_Byte2_30 : 8|8@1+ (1,0) [0|255] ""  PC
 SG_ S2P_Cfg12_SW_Ver_Byte3_30 : 16|8@1+ (1,0) [0|255] ""  PC
 SG_ S2P_Cfg12_SW_Ver_Byte4_30 : 24|8@1+ (1,0) [0|255] ""  PC
 SG_ S2P_Cfg12_SW_Ver_Byte5_30 : 32|8@1+ (1,0) [0|255] ""  PC
 SG_ S2P_Cfg12_SW_Ver_Byte6_30 : 40|8@1+ (1,0) [0|255] ""  PC
 SG_ S2P_Cfg12_SW_Ver_Byte7_30 : 48|8@1+ (1,0) [0|255] ""  PC
 SG_ S2P_Cfg12_SW_Ver_Byte8_30 : 56|8@1+ (1,0) [0|255] ""  PC

BO_ 2418601567 S2P_Cfg12__31: 8 SBMU
 SG_ S2P_Cfg12_SW_Ver_Byte1_31 : 0|8@1+ (1,0) [0|255] ""  PC
 SG_ S2P_Cfg12_SW_Ver_Byte2_31 : 8|8@1+ (1,0) [0|255] ""  PC
 SG_ S2P_Cfg12_SW_Ver_Byte3_31 : 16|8@1+ (1,0) [0|255] ""  PC
 SG_ S2P_Cfg12_SW_Ver_Byte4_31 : 24|8@1+ (1,0) [0|255] ""  PC
 SG_ S2P_Cfg12_SW_Ver_Byte5_31 : 32|8@1+ (1,0) [0|255] ""  PC
 SG_ S2P_Cfg12_SW_Ver_Byte6_31 : 40|8@1+ (1,0) [0|255] ""  PC
 SG_ S2P_Cfg12_SW_Ver_Byte7_31 : 48|8@1+ (1,0) [0|255] ""  PC
 SG_ S2P_Cfg12_SW_Ver_Byte8_31 : 56|8@1+ (1,0) [0|255] ""  PC

BO_ 2418601568 S2P_Cfg12__32: 8 SBMU
 SG_ S2P_Cfg12_SW_Ver_Byte1_32 : 0|8@1+ (1,0) [0|255] ""  PC
 SG_ S2P_Cfg12_SW_Ver_Byte2_32 : 8|8@1+ (1,0) [0|255] ""  PC
 SG_ S2P_Cfg12_SW_Ver_Byte3_32 : 16|8@1+ (1,0) [0|255] ""  PC
 SG_ S2P_Cfg12_SW_Ver_Byte4_32 : 24|8@1+ (1,0) [0|255] ""  PC
 SG_ S2P_Cfg12_SW_Ver_Byte5_32 : 32|8@1+ (1,0) [0|255] ""  PC
 SG_ S2P_Cfg12_SW_Ver_Byte6_32 : 40|8@1+ (1,0) [0|255] ""  PC
 SG_ S2P_Cfg12_SW_Ver_Byte7_32 : 48|8@1+ (1,0) [0|255] ""  PC
 SG_ S2P_Cfg12_SW_Ver_Byte8_32 : 56|8@1+ (1,0) [0|255] ""  PC

BO_ 2418601569 S2P_Cfg12__33: 8 SBMU
 SG_ S2P_Cfg12_SW_Ver_Byte1_33 : 0|8@1+ (1,0) [0|255] ""  PC
 SG_ S2P_Cfg12_SW_Ver_Byte2_33 : 8|8@1+ (1,0) [0|255] ""  PC
 SG_ S2P_Cfg12_SW_Ver_Byte3_33 : 16|8@1+ (1,0) [0|255] ""  PC
 SG_ S2P_Cfg12_SW_Ver_Byte4_33 : 24|8@1+ (1,0) [0|255] ""  PC
 SG_ S2P_Cfg12_SW_Ver_Byte5_33 : 32|8@1+ (1,0) [0|255] ""  PC
 SG_ S2P_Cfg12_SW_Ver_Byte6_33 : 40|8@1+ (1,0) [0|255] ""  PC
 SG_ S2P_Cfg12_SW_Ver_Byte7_33 : 48|8@1+ (1,0) [0|255] ""  PC
 SG_ S2P_Cfg12_SW_Ver_Byte8_33 : 56|8@1+ (1,0) [0|255] ""  PC

BO_ 2418601570 S2P_Cfg12__34: 8 SBMU
 SG_ S2P_Cfg12_SW_Ver_Byte1_34 : 0|8@1+ (1,0) [0|255] ""  PC
 SG_ S2P_Cfg12_SW_Ver_Byte2_34 : 8|8@1+ (1,0) [0|255] ""  PC
 SG_ S2P_Cfg12_SW_Ver_Byte3_34 : 16|8@1+ (1,0) [0|255] ""  PC
 SG_ S2P_Cfg12_SW_Ver_Byte4_34 : 24|8@1+ (1,0) [0|255] ""  PC
 SG_ S2P_Cfg12_SW_Ver_Byte5_34 : 32|8@1+ (1,0) [0|255] ""  PC
 SG_ S2P_Cfg12_SW_Ver_Byte6_34 : 40|8@1+ (1,0) [0|255] ""  PC
 SG_ S2P_Cfg12_SW_Ver_Byte7_34 : 48|8@1+ (1,0) [0|255] ""  PC
 SG_ S2P_Cfg12_SW_Ver_Byte8_34 : 56|8@1+ (1,0) [0|255] ""  PC

BO_ 2418601571 S2P_Cfg12__35: 8 SBMU
 SG_ S2P_Cfg12_SW_Ver_Byte1_35 : 0|8@1+ (1,0) [0|255] ""  PC
 SG_ S2P_Cfg12_SW_Ver_Byte2_35 : 8|8@1+ (1,0) [0|255] ""  PC
 SG_ S2P_Cfg12_SW_Ver_Byte3_35 : 16|8@1+ (1,0) [0|255] ""  PC
 SG_ S2P_Cfg12_SW_Ver_Byte4_35 : 24|8@1+ (1,0) [0|255] ""  PC
 SG_ S2P_Cfg12_SW_Ver_Byte5_35 : 32|8@1+ (1,0) [0|255] ""  PC
 SG_ S2P_Cfg12_SW_Ver_Byte6_35 : 40|8@1+ (1,0) [0|255] ""  PC
 SG_ S2P_Cfg12_SW_Ver_Byte7_35 : 48|8@1+ (1,0) [0|255] ""  PC
 SG_ S2P_Cfg12_SW_Ver_Byte8_35 : 56|8@1+ (1,0) [0|255] ""  PC

BO_ 2418601572 S2P_Cfg12__36: 8 SBMU
 SG_ S2P_Cfg12_SW_Ver_Byte1_36 : 0|8@1+ (1,0) [0|255] ""  PC
 SG_ S2P_Cfg12_SW_Ver_Byte2_36 : 8|8@1+ (1,0) [0|255] ""  PC
 SG_ S2P_Cfg12_SW_Ver_Byte3_36 : 16|8@1+ (1,0) [0|255] ""  PC
 SG_ S2P_Cfg12_SW_Ver_Byte4_36 : 24|8@1+ (1,0) [0|255] ""  PC
 SG_ S2P_Cfg12_SW_Ver_Byte5_36 : 32|8@1+ (1,0) [0|255] ""  PC
 SG_ S2P_Cfg12_SW_Ver_Byte6_36 : 40|8@1+ (1,0) [0|255] ""  PC
 SG_ S2P_Cfg12_SW_Ver_Byte7_36 : 48|8@1+ (1,0) [0|255] ""  PC
 SG_ S2P_Cfg12_SW_Ver_Byte8_36 : 56|8@1+ (1,0) [0|255] ""  PC

BO_ 2418601573 S2P_Cfg12__37: 8 SBMU
 SG_ S2P_Cfg12_SW_Ver_Byte1_37 : 0|8@1+ (1,0) [0|255] ""  PC
 SG_ S2P_Cfg12_SW_Ver_Byte2_37 : 8|8@1+ (1,0) [0|255] ""  PC
 SG_ S2P_Cfg12_SW_Ver_Byte3_37 : 16|8@1+ (1,0) [0|255] ""  PC
 SG_ S2P_Cfg12_SW_Ver_Byte4_37 : 24|8@1+ (1,0) [0|255] ""  PC
 SG_ S2P_Cfg12_SW_Ver_Byte5_37 : 32|8@1+ (1,0) [0|255] ""  PC
 SG_ S2P_Cfg12_SW_Ver_Byte6_37 : 40|8@1+ (1,0) [0|255] ""  PC
 SG_ S2P_Cfg12_SW_Ver_Byte7_37 : 48|8@1+ (1,0) [0|255] ""  PC
 SG_ S2P_Cfg12_SW_Ver_Byte8_37 : 56|8@1+ (1,0) [0|255] ""  PC

CM_ SG_ 2148892563 U2T_BMS_ControlMode_2 "BMS请求2号TMS设定模式";
CM_ SG_ 2148892563 T2U_TMS_RunState_2 "2号TMS运行状态";
CM_ SG_ 2148892563 T2U_TMS_FaultCode_2 "2号TMS故障码";
CM_ SG_ 2148892563 T2U_TMS_FaultLevel_2 "2号TMS故障码等级";
CM_ SG_ 2148892563 U2T_BMS_TmptSetPoint_2 "2号BMS设定温度";
CM_ SG_ 2148892563 T2U_TMS_OutWaterTemp_2 "2号TMS出水温度";
CM_ SG_ 2148892563 T2U_TMS_BackWaterTemp_2 "2号TMS回水温度";
CM_ SG_ 2148892563 T2U_TMS_EnvTemp_2 "2号TMS环境温度";
CM_ SG_ 2148892563 T2U_TMS_K2_HVRealyState_2 "预留";
CM_ SG_ 2148892563 M2P_TMS_OvrTmpLwFltLvl3_2_03 "2号TMS_制冷模式保护";
CM_ SG_ 2148892564 U2T_BMS_ControlMode_2 "BMS请求2号TMS设定模式";
CM_ SG_ 2148892564 T2U_TMS_RunState_2 "2号TMS运行状态";
CM_ SG_ 2148892564 T2U_TMS_FaultCode_2 "2号TMS故障码";
CM_ SG_ 2148892564 T2U_TMS_FaultLevel_2 "2号TMS故障码等级";
CM_ SG_ 2148892564 U2T_BMS_TmptSetPoint_2 "2号BMS设定温度";
CM_ SG_ 2148892564 T2U_TMS_OutWaterTemp_2 "2号TMS出水温度";
CM_ SG_ 2148892564 T2U_TMS_BackWaterTemp_2 "2号TMS回水温度";
CM_ SG_ 2148892564 T2U_TMS_EnvTemp_2 "2号TMS环境温度";
CM_ SG_ 2148892564 T2U_TMS_K2_HVRealyState_2 "预留";
CM_ SG_ 2148892564 M2P_TMS_OvrTmpLwFltLvl3_2_04 "2号TMS_制冷模式保护";
CM_ SG_ 2148892565 U2T_BMS_ControlMode_2 "BMS请求2号TMS设定模式";
CM_ SG_ 2148892565 T2U_TMS_RunState_2 "2号TMS运行状态";
CM_ SG_ 2148892565 T2U_TMS_FaultCode_2 "2号TMS故障码";
CM_ SG_ 2148892565 T2U_TMS_FaultLevel_2 "2号TMS故障码等级";
CM_ SG_ 2148892565 U2T_BMS_TmptSetPoint_2 "2号BMS设定温度";
CM_ SG_ 2148892565 T2U_TMS_OutWaterTemp_2 "2号TMS出水温度";
CM_ SG_ 2148892565 T2U_TMS_BackWaterTemp_2 "2号TMS回水温度";
CM_ SG_ 2148892565 T2U_TMS_EnvTemp_2 "2号TMS环境温度";
CM_ SG_ 2148892565 T2U_TMS_K2_HVRealyState_2 "预留";
CM_ SG_ 2148892565 M2P_TMS_OvrTmpLwFltLvl3_2_05 "2号TMS_制冷模式保护";
CM_ SG_ 2148892566 U2T_BMS_ControlMode_2 "BMS请求2号TMS设定模式";
CM_ SG_ 2148892566 T2U_TMS_RunState_2 "2号TMS运行状态";
CM_ SG_ 2148892566 T2U_TMS_FaultCode_2 "2号TMS故障码";
CM_ SG_ 2148892566 T2U_TMS_FaultLevel_2 "2号TMS故障码等级";
CM_ SG_ 2148892566 U2T_BMS_TmptSetPoint_2 "2号BMS设定温度";
CM_ SG_ 2148892566 T2U_TMS_OutWaterTemp_2 "2号TMS出水温度";
CM_ SG_ 2148892566 T2U_TMS_BackWaterTemp_2 "2号TMS回水温度";
CM_ SG_ 2148892566 T2U_TMS_EnvTemp_2 "2号TMS环境温度";
CM_ SG_ 2148892566 T2U_TMS_K2_HVRealyState_2 "预留";
CM_ SG_ 2148892566 M2P_TMS_OvrTmpLwFltLvl3_2_06 "2号TMS_制冷模式保护";
CM_ SG_ 2148892567 U2T_BMS_ControlMode_2 "BMS请求2号TMS设定模式";
CM_ SG_ 2148892567 T2U_TMS_RunState_2 "2号TMS运行状态";
CM_ SG_ 2148892567 T2U_TMS_FaultCode_2 "2号TMS故障码";
CM_ SG_ 2148892567 T2U_TMS_FaultLevel_2 "2号TMS故障码等级";
CM_ SG_ 2148892567 U2T_BMS_TmptSetPoint_2 "2号BMS设定温度";
CM_ SG_ 2148892567 T2U_TMS_OutWaterTemp_2 "2号TMS出水温度";
CM_ SG_ 2148892567 T2U_TMS_BackWaterTemp_2 "2号TMS回水温度";
CM_ SG_ 2148892567 T2U_TMS_EnvTemp_2 "2号TMS环境温度";
CM_ SG_ 2148892567 T2U_TMS_K2_HVRealyState_2 "预留";
CM_ SG_ 2148892567 M2P_TMS_OvrTmpLwFltLvl3_2_07 "2号TMS_制冷模式保护";
CM_ SG_ 2148892568 U2T_BMS_ControlMode_2 "BMS请求2号TMS设定模式";
CM_ SG_ 2148892568 T2U_TMS_RunState_2 "2号TMS运行状态";
CM_ SG_ 2148892568 T2U_TMS_FaultCode_2 "2号TMS故障码";
CM_ SG_ 2148892568 T2U_TMS_FaultLevel_2 "2号TMS故障码等级";
CM_ SG_ 2148892568 U2T_BMS_TmptSetPoint_2 "2号BMS设定温度";
CM_ SG_ 2148892568 T2U_TMS_OutWaterTemp_2 "2号TMS出水温度";
CM_ SG_ 2148892568 T2U_TMS_BackWaterTemp_2 "2号TMS回水温度";
CM_ SG_ 2148892568 T2U_TMS_EnvTemp_2 "2号TMS环境温度";
CM_ SG_ 2148892568 T2U_TMS_K2_HVRealyState_2 "预留";
CM_ SG_ 2148892568 M2P_TMS_OvrTmpLwFltLvl3_2_08 "2号TMS_制冷模式保护";
CM_ SG_ 2148892569 U2T_BMS_ControlMode_2 "BMS请求2号TMS设定模式";
CM_ SG_ 2148892569 T2U_TMS_RunState_2 "2号TMS运行状态";
CM_ SG_ 2148892569 T2U_TMS_FaultCode_2 "2号TMS故障码";
CM_ SG_ 2148892569 T2U_TMS_FaultLevel_2 "2号TMS故障码等级";
CM_ SG_ 2148892569 U2T_BMS_TmptSetPoint_2 "2号BMS设定温度";
CM_ SG_ 2148892569 T2U_TMS_OutWaterTemp_2 "2号TMS出水温度";
CM_ SG_ 2148892569 T2U_TMS_BackWaterTemp_2 "2号TMS回水温度";
CM_ SG_ 2148892569 T2U_TMS_EnvTemp_2 "2号TMS环境温度";
CM_ SG_ 2148892569 T2U_TMS_K2_HVRealyState_2 "预留";
CM_ SG_ 2148892569 M2P_TMS_OvrTmpLwFltLvl3_2_09 "2号TMS_制冷模式保护";
CM_ SG_ 2148892570 U2T_BMS_ControlMode_2 "BMS请求2号TMS设定模式";
CM_ SG_ 2148892570 T2U_TMS_RunState_2 "2号TMS运行状态";
CM_ SG_ 2148892570 T2U_TMS_FaultCode_2 "2号TMS故障码";
CM_ SG_ 2148892570 T2U_TMS_FaultLevel_2 "2号TMS故障码等级";
CM_ SG_ 2148892570 U2T_BMS_TmptSetPoint_2 "2号BMS设定温度";
CM_ SG_ 2148892570 T2U_TMS_OutWaterTemp_2 "2号TMS出水温度";
CM_ SG_ 2148892570 T2U_TMS_BackWaterTemp_2 "2号TMS回水温度";
CM_ SG_ 2148892570 T2U_TMS_EnvTemp_2 "2号TMS环境温度";
CM_ SG_ 2148892570 T2U_TMS_K2_HVRealyState_2 "预留";
CM_ SG_ 2148892570 M2P_TMS_OvrTmpLwFltLvl3_2_10 "2号TMS_制冷模式保护";
CM_ SG_ 2148892571 U2T_BMS_ControlMode_2 "BMS请求2号TMS设定模式";
CM_ SG_ 2148892571 T2U_TMS_RunState_2 "2号TMS运行状态";
CM_ SG_ 2148892571 T2U_TMS_FaultCode_2 "2号TMS故障码";
CM_ SG_ 2148892571 T2U_TMS_FaultLevel_2 "2号TMS故障码等级";
CM_ SG_ 2148892571 U2T_BMS_TmptSetPoint_2 "2号BMS设定温度";
CM_ SG_ 2148892571 T2U_TMS_OutWaterTemp_2 "2号TMS出水温度";
CM_ SG_ 2148892571 T2U_TMS_BackWaterTemp_2 "2号TMS回水温度";
CM_ SG_ 2148892571 T2U_TMS_EnvTemp_2 "2号TMS环境温度";
CM_ SG_ 2148892571 T2U_TMS_K2_HVRealyState_2 "预留";
CM_ SG_ 2148892571 M2P_TMS_OvrTmpLwFltLvl3_2_11 "2号TMS_制冷模式保护";
CM_ SG_ 2148892572 U2T_BMS_ControlMode_2 "BMS请求2号TMS设定模式";
CM_ SG_ 2148892572 T2U_TMS_RunState_2 "2号TMS运行状态";
CM_ SG_ 2148892572 T2U_TMS_FaultCode_2 "2号TMS故障码";
CM_ SG_ 2148892572 T2U_TMS_FaultLevel_2 "2号TMS故障码等级";
CM_ SG_ 2148892572 U2T_BMS_TmptSetPoint_2 "2号BMS设定温度";
CM_ SG_ 2148892572 T2U_TMS_OutWaterTemp_2 "2号TMS出水温度";
CM_ SG_ 2148892572 T2U_TMS_BackWaterTemp_2 "2号TMS回水温度";
CM_ SG_ 2148892572 T2U_TMS_EnvTemp_2 "2号TMS环境温度";
CM_ SG_ 2148892572 T2U_TMS_K2_HVRealyState_2 "预留";
CM_ SG_ 2148892572 M2P_TMS_OvrTmpLwFltLvl3_2_12 "2号TMS_制冷模式保护";
CM_ SG_ 2148892573 U2T_BMS_ControlMode_2 "BMS请求2号TMS设定模式";
CM_ SG_ 2148892573 T2U_TMS_RunState_2 "2号TMS运行状态";
CM_ SG_ 2148892573 T2U_TMS_FaultCode_2 "2号TMS故障码";
CM_ SG_ 2148892573 T2U_TMS_FaultLevel_2 "2号TMS故障码等级";
CM_ SG_ 2148892573 U2T_BMS_TmptSetPoint_2 "2号BMS设定温度";
CM_ SG_ 2148892573 T2U_TMS_OutWaterTemp_2 "2号TMS出水温度";
CM_ SG_ 2148892573 T2U_TMS_BackWaterTemp_2 "2号TMS回水温度";
CM_ SG_ 2148892573 T2U_TMS_EnvTemp_2 "2号TMS环境温度";
CM_ SG_ 2148892573 T2U_TMS_K2_HVRealyState_2 "预留";
CM_ SG_ 2148892573 M2P_TMS_OvrTmpLwFltLvl3_2_13 "2号TMS_制冷模式保护";
CM_ SG_ 2148892574 U2T_BMS_ControlMode_2 "BMS请求2号TMS设定模式";
CM_ SG_ 2148892574 T2U_TMS_RunState_2 "2号TMS运行状态";
CM_ SG_ 2148892574 T2U_TMS_FaultCode_2 "2号TMS故障码";
CM_ SG_ 2148892574 T2U_TMS_FaultLevel_2 "2号TMS故障码等级";
CM_ SG_ 2148892574 U2T_BMS_TmptSetPoint_2 "2号BMS设定温度";
CM_ SG_ 2148892574 T2U_TMS_OutWaterTemp_2 "2号TMS出水温度";
CM_ SG_ 2148892574 T2U_TMS_BackWaterTemp_2 "2号TMS回水温度";
CM_ SG_ 2148892574 T2U_TMS_EnvTemp_2 "2号TMS环境温度";
CM_ SG_ 2148892574 T2U_TMS_K2_HVRealyState_2 "预留";
CM_ SG_ 2148892574 M2P_TMS_OvrTmpLwFltLvl3_2_14 "2号TMS_制冷模式保护";
CM_ SG_ 2148892575 U2T_BMS_ControlMode_2 "BMS请求2号TMS设定模式";
CM_ SG_ 2148892575 T2U_TMS_RunState_2 "2号TMS运行状态";
CM_ SG_ 2148892575 T2U_TMS_FaultCode_2 "2号TMS故障码";
CM_ SG_ 2148892575 T2U_TMS_FaultLevel_2 "2号TMS故障码等级";
CM_ SG_ 2148892575 U2T_BMS_TmptSetPoint_2 "2号BMS设定温度";
CM_ SG_ 2148892575 T2U_TMS_OutWaterTemp_2 "2号TMS出水温度";
CM_ SG_ 2148892575 T2U_TMS_BackWaterTemp_2 "2号TMS回水温度";
CM_ SG_ 2148892575 T2U_TMS_EnvTemp_2 "2号TMS环境温度";
CM_ SG_ 2148892575 T2U_TMS_K2_HVRealyState_2 "预留";
CM_ SG_ 2148892575 M2P_TMS_OvrTmpLwFltLvl3_2_15 "2号TMS_制冷模式保护";
CM_ SG_ 2148892576 U2T_BMS_ControlMode_2 "BMS请求2号TMS设定模式";
CM_ SG_ 2148892576 T2U_TMS_RunState_2 "2号TMS运行状态";
CM_ SG_ 2148892576 T2U_TMS_FaultCode_2 "2号TMS故障码";
CM_ SG_ 2148892576 T2U_TMS_FaultLevel_2 "2号TMS故障码等级";
CM_ SG_ 2148892576 U2T_BMS_TmptSetPoint_2 "2号BMS设定温度";
CM_ SG_ 2148892576 T2U_TMS_OutWaterTemp_2 "2号TMS出水温度";
CM_ SG_ 2148892576 T2U_TMS_BackWaterTemp_2 "2号TMS回水温度";
CM_ SG_ 2148892576 T2U_TMS_EnvTemp_2 "2号TMS环境温度";
CM_ SG_ 2148892576 T2U_TMS_K2_HVRealyState_2 "预留";
CM_ SG_ 2148892576 M2P_TMS_OvrTmpLwFltLvl3_2_16 "2号TMS_制冷模式保护";
CM_ SG_ 2148892577 U2T_BMS_ControlMode_2 "BMS请求2号TMS设定模式";
CM_ SG_ 2148892577 T2U_TMS_RunState_2 "2号TMS运行状态";
CM_ SG_ 2148892577 T2U_TMS_FaultCode_2 "2号TMS故障码";
CM_ SG_ 2148892577 T2U_TMS_FaultLevel_2 "2号TMS故障码等级";
CM_ SG_ 2148892577 U2T_BMS_TmptSetPoint_2 "2号BMS设定温度";
CM_ SG_ 2148892577 T2U_TMS_OutWaterTemp_2 "2号TMS出水温度";
CM_ SG_ 2148892577 T2U_TMS_BackWaterTemp_2 "2号TMS回水温度";
CM_ SG_ 2148892577 T2U_TMS_EnvTemp_2 "2号TMS环境温度";
CM_ SG_ 2148892577 T2U_TMS_K2_HVRealyState_2 "预留";
CM_ SG_ 2148892577 M2P_TMS_OvrTmpLwFltLvl3_2_17 "2号TMS_制冷模式保护";
CM_ SG_ 2148892578 U2T_BMS_ControlMode_2 "BMS请求2号TMS设定模式";
CM_ SG_ 2148892578 T2U_TMS_RunState_2 "2号TMS运行状态";
CM_ SG_ 2148892578 T2U_TMS_FaultCode_2 "2号TMS故障码";
CM_ SG_ 2148892578 T2U_TMS_FaultLevel_2 "2号TMS故障码等级";
CM_ SG_ 2148892578 U2T_BMS_TmptSetPoint_2 "2号BMS设定温度";
CM_ SG_ 2148892578 T2U_TMS_OutWaterTemp_2 "2号TMS出水温度";
CM_ SG_ 2148892578 T2U_TMS_BackWaterTemp_2 "2号TMS回水温度";
CM_ SG_ 2148892578 T2U_TMS_EnvTemp_2 "2号TMS环境温度";
CM_ SG_ 2148892578 T2U_TMS_K2_HVRealyState_2 "预留";
CM_ SG_ 2148892578 M2P_TMS_OvrTmpLwFltLvl3_2_18 "2号TMS_制冷模式保护";
CM_ SG_ 2148892579 U2T_BMS_ControlMode_2 "BMS请求2号TMS设定模式";
CM_ SG_ 2148892579 T2U_TMS_RunState_2 "2号TMS运行状态";
CM_ SG_ 2148892579 T2U_TMS_FaultCode_2 "2号TMS故障码";
CM_ SG_ 2148892579 T2U_TMS_FaultLevel_2 "2号TMS故障码等级";
CM_ SG_ 2148892579 U2T_BMS_TmptSetPoint_2 "2号BMS设定温度";
CM_ SG_ 2148892579 T2U_TMS_OutWaterTemp_2 "2号TMS出水温度";
CM_ SG_ 2148892579 T2U_TMS_BackWaterTemp_2 "2号TMS回水温度";
CM_ SG_ 2148892579 T2U_TMS_EnvTemp_2 "2号TMS环境温度";
CM_ SG_ 2148892579 T2U_TMS_K2_HVRealyState_2 "预留";
CM_ SG_ 2148892579 M2P_TMS_OvrTmpLwFltLvl3_2_19 "2号TMS_制冷模式保护";
CM_ SG_ 2148892580 U2T_BMS_ControlMode_2 "BMS请求2号TMS设定模式";
CM_ SG_ 2148892580 T2U_TMS_RunState_2 "2号TMS运行状态";
CM_ SG_ 2148892580 T2U_TMS_FaultCode_2 "2号TMS故障码";
CM_ SG_ 2148892580 T2U_TMS_FaultLevel_2 "2号TMS故障码等级";
CM_ SG_ 2148892580 U2T_BMS_TmptSetPoint_2 "2号BMS设定温度";
CM_ SG_ 2148892580 T2U_TMS_OutWaterTemp_2 "2号TMS出水温度";
CM_ SG_ 2148892580 T2U_TMS_BackWaterTemp_2 "2号TMS回水温度";
CM_ SG_ 2148892580 T2U_TMS_EnvTemp_2 "2号TMS环境温度";
CM_ SG_ 2148892580 T2U_TMS_K2_HVRealyState_2 "预留";
CM_ SG_ 2148892580 M2P_TMS_OvrTmpLwFltLvl3_2_20 "2号TMS_制冷模式保护";
CM_ SG_ 2148892581 U2T_BMS_ControlMode_2 "BMS请求2号TMS设定模式";
CM_ SG_ 2148892581 T2U_TMS_RunState_2 "2号TMS运行状态";
CM_ SG_ 2148892581 T2U_TMS_FaultCode_2 "2号TMS故障码";
CM_ SG_ 2148892581 T2U_TMS_FaultLevel_2 "2号TMS故障码等级";
CM_ SG_ 2148892581 U2T_BMS_TmptSetPoint_2 "2号BMS设定温度";
CM_ SG_ 2148892581 T2U_TMS_OutWaterTemp_2 "2号TMS出水温度";
CM_ SG_ 2148892581 T2U_TMS_BackWaterTemp_2 "2号TMS回水温度";
CM_ SG_ 2148892581 T2U_TMS_EnvTemp_2 "2号TMS环境温度";
CM_ SG_ 2148892581 T2U_TMS_K2_HVRealyState_2 "预留";
CM_ SG_ 2148892581 M2P_TMS_OvrTmpLwFltLvl3_2_21 "2号TMS_制冷模式保护";
CM_ SG_ 2148892582 U2T_BMS_ControlMode_2 "BMS请求2号TMS设定模式";
CM_ SG_ 2148892582 T2U_TMS_RunState_2 "2号TMS运行状态";
CM_ SG_ 2148892582 T2U_TMS_FaultCode_2 "2号TMS故障码";
CM_ SG_ 2148892582 T2U_TMS_FaultLevel_2 "2号TMS故障码等级";
CM_ SG_ 2148892582 U2T_BMS_TmptSetPoint_2 "2号BMS设定温度";
CM_ SG_ 2148892582 T2U_TMS_OutWaterTemp_2 "2号TMS出水温度";
CM_ SG_ 2148892582 T2U_TMS_BackWaterTemp_2 "2号TMS回水温度";
CM_ SG_ 2148892582 T2U_TMS_EnvTemp_2 "2号TMS环境温度";
CM_ SG_ 2148892582 T2U_TMS_K2_HVRealyState_2 "预留";
CM_ SG_ 2148892582 M2P_TMS_OvrTmpLwFltLvl3_2_22 "2号TMS_制冷模式保护";
CM_ SG_ 2148892583 U2T_BMS_ControlMode_2 "BMS请求2号TMS设定模式";
CM_ SG_ 2148892583 T2U_TMS_RunState_2 "2号TMS运行状态";
CM_ SG_ 2148892583 T2U_TMS_FaultCode_2 "2号TMS故障码";
CM_ SG_ 2148892583 T2U_TMS_FaultLevel_2 "2号TMS故障码等级";
CM_ SG_ 2148892583 U2T_BMS_TmptSetPoint_2 "2号BMS设定温度";
CM_ SG_ 2148892583 T2U_TMS_OutWaterTemp_2 "2号TMS出水温度";
CM_ SG_ 2148892583 T2U_TMS_BackWaterTemp_2 "2号TMS回水温度";
CM_ SG_ 2148892583 T2U_TMS_EnvTemp_2 "2号TMS环境温度";
CM_ SG_ 2148892583 T2U_TMS_K2_HVRealyState_2 "预留";
CM_ SG_ 2148892583 M2P_TMS_OvrTmpLwFltLvl3_2_23 "2号TMS_制冷模式保护";
CM_ SG_ 2148892584 U2T_BMS_ControlMode_2 "BMS请求2号TMS设定模式";
CM_ SG_ 2148892584 T2U_TMS_RunState_2 "2号TMS运行状态";
CM_ SG_ 2148892584 T2U_TMS_FaultCode_2 "2号TMS故障码";
CM_ SG_ 2148892584 T2U_TMS_FaultLevel_2 "2号TMS故障码等级";
CM_ SG_ 2148892584 U2T_BMS_TmptSetPoint_2 "2号BMS设定温度";
CM_ SG_ 2148892584 T2U_TMS_OutWaterTemp_2 "2号TMS出水温度";
CM_ SG_ 2148892584 T2U_TMS_BackWaterTemp_2 "2号TMS回水温度";
CM_ SG_ 2148892584 T2U_TMS_EnvTemp_2 "2号TMS环境温度";
CM_ SG_ 2148892584 T2U_TMS_K2_HVRealyState_2 "预留";
CM_ SG_ 2148892584 M2P_TMS_OvrTmpLwFltLvl3_2_24 "2号TMS_制冷模式保护";
CM_ SG_ 2148892585 U2T_BMS_ControlMode_2 "BMS请求2号TMS设定模式";
CM_ SG_ 2148892585 T2U_TMS_RunState_2 "2号TMS运行状态";
CM_ SG_ 2148892585 T2U_TMS_FaultCode_2 "2号TMS故障码";
CM_ SG_ 2148892585 T2U_TMS_FaultLevel_2 "2号TMS故障码等级";
CM_ SG_ 2148892585 U2T_BMS_TmptSetPoint_2 "2号BMS设定温度";
CM_ SG_ 2148892585 T2U_TMS_OutWaterTemp_2 "2号TMS出水温度";
CM_ SG_ 2148892585 T2U_TMS_BackWaterTemp_2 "2号TMS回水温度";
CM_ SG_ 2148892585 T2U_TMS_EnvTemp_2 "2号TMS环境温度";
CM_ SG_ 2148892585 T2U_TMS_K2_HVRealyState_2 "预留";
CM_ SG_ 2148892585 M2P_TMS_OvrTmpLwFltLvl3_2_25 "2号TMS_制冷模式保护";
CM_ SG_ 2148892586 U2T_BMS_ControlMode_2 "BMS请求2号TMS设定模式";
CM_ SG_ 2148892586 T2U_TMS_RunState_2 "2号TMS运行状态";
CM_ SG_ 2148892586 T2U_TMS_FaultCode_2 "2号TMS故障码";
CM_ SG_ 2148892586 T2U_TMS_FaultLevel_2 "2号TMS故障码等级";
CM_ SG_ 2148892586 U2T_BMS_TmptSetPoint_2 "2号BMS设定温度";
CM_ SG_ 2148892586 T2U_TMS_OutWaterTemp_2 "2号TMS出水温度";
CM_ SG_ 2148892586 T2U_TMS_BackWaterTemp_2 "2号TMS回水温度";
CM_ SG_ 2148892586 T2U_TMS_EnvTemp_2 "2号TMS环境温度";
CM_ SG_ 2148892586 T2U_TMS_K2_HVRealyState_2 "预留";
CM_ SG_ 2148892586 M2P_TMS_OvrTmpLwFltLvl3_2_26 "2号TMS_制冷模式保护";
CM_ SG_ 2148892587 U2T_BMS_ControlMode_2 "BMS请求2号TMS设定模式";
CM_ SG_ 2148892587 T2U_TMS_RunState_2 "2号TMS运行状态";
CM_ SG_ 2148892587 T2U_TMS_FaultCode_2 "2号TMS故障码";
CM_ SG_ 2148892587 T2U_TMS_FaultLevel_2 "2号TMS故障码等级";
CM_ SG_ 2148892587 U2T_BMS_TmptSetPoint_2 "2号BMS设定温度";
CM_ SG_ 2148892587 T2U_TMS_OutWaterTemp_2 "2号TMS出水温度";
CM_ SG_ 2148892587 T2U_TMS_BackWaterTemp_2 "2号TMS回水温度";
CM_ SG_ 2148892587 T2U_TMS_EnvTemp_2 "2号TMS环境温度";
CM_ SG_ 2148892587 T2U_TMS_K2_HVRealyState_2 "预留";
CM_ SG_ 2148892587 M2P_TMS_OvrTmpLwFltLvl3_2_27 "2号TMS_制冷模式保护";
CM_ SG_ 2148892588 U2T_BMS_ControlMode_2 "BMS请求2号TMS设定模式";
CM_ SG_ 2148892588 T2U_TMS_RunState_2 "2号TMS运行状态";
CM_ SG_ 2148892588 T2U_TMS_FaultCode_2 "2号TMS故障码";
CM_ SG_ 2148892588 T2U_TMS_FaultLevel_2 "2号TMS故障码等级";
CM_ SG_ 2148892588 U2T_BMS_TmptSetPoint_2 "2号BMS设定温度";
CM_ SG_ 2148892588 T2U_TMS_OutWaterTemp_2 "2号TMS出水温度";
CM_ SG_ 2148892588 T2U_TMS_BackWaterTemp_2 "2号TMS回水温度";
CM_ SG_ 2148892588 T2U_TMS_EnvTemp_2 "2号TMS环境温度";
CM_ SG_ 2148892588 T2U_TMS_K2_HVRealyState_2 "预留";
CM_ SG_ 2148892588 M2P_TMS_OvrTmpLwFltLvl3_2_28 "2号TMS_制冷模式保护";
CM_ SG_ 2148892589 U2T_BMS_ControlMode_2 "BMS请求2号TMS设定模式";
CM_ SG_ 2148892589 T2U_TMS_RunState_2 "2号TMS运行状态";
CM_ SG_ 2148892589 T2U_TMS_FaultCode_2 "2号TMS故障码";
CM_ SG_ 2148892589 T2U_TMS_FaultLevel_2 "2号TMS故障码等级";
CM_ SG_ 2148892589 U2T_BMS_TmptSetPoint_2 "2号BMS设定温度";
CM_ SG_ 2148892589 T2U_TMS_OutWaterTemp_2 "2号TMS出水温度";
CM_ SG_ 2148892589 T2U_TMS_BackWaterTemp_2 "2号TMS回水温度";
CM_ SG_ 2148892589 T2U_TMS_EnvTemp_2 "2号TMS环境温度";
CM_ SG_ 2148892589 T2U_TMS_K2_HVRealyState_2 "预留";
CM_ SG_ 2148892589 M2P_TMS_OvrTmpLwFltLvl3_2_29 "2号TMS_制冷模式保护";
CM_ SG_ 2148892590 U2T_BMS_ControlMode_2 "BMS请求2号TMS设定模式";
CM_ SG_ 2148892590 T2U_TMS_RunState_2 "2号TMS运行状态";
CM_ SG_ 2148892590 T2U_TMS_FaultCode_2 "2号TMS故障码";
CM_ SG_ 2148892590 T2U_TMS_FaultLevel_2 "2号TMS故障码等级";
CM_ SG_ 2148892590 U2T_BMS_TmptSetPoint_2 "2号BMS设定温度";
CM_ SG_ 2148892590 T2U_TMS_OutWaterTemp_2 "2号TMS出水温度";
CM_ SG_ 2148892590 T2U_TMS_BackWaterTemp_2 "2号TMS回水温度";
CM_ SG_ 2148892590 T2U_TMS_EnvTemp_2 "2号TMS环境温度";
CM_ SG_ 2148892590 T2U_TMS_K2_HVRealyState_2 "预留";
CM_ SG_ 2148892590 M2P_TMS_OvrTmpLwFltLvl3_2_30 "2号TMS_制冷模式保护";
CM_ SG_ 2148892591 U2T_BMS_ControlMode_2 "BMS请求2号TMS设定模式";
CM_ SG_ 2148892591 T2U_TMS_RunState_2 "2号TMS运行状态";
CM_ SG_ 2148892591 T2U_TMS_FaultCode_2 "2号TMS故障码";
CM_ SG_ 2148892591 T2U_TMS_FaultLevel_2 "2号TMS故障码等级";
CM_ SG_ 2148892591 U2T_BMS_TmptSetPoint_2 "2号BMS设定温度";
CM_ SG_ 2148892591 T2U_TMS_OutWaterTemp_2 "2号TMS出水温度";
CM_ SG_ 2148892591 T2U_TMS_BackWaterTemp_2 "2号TMS回水温度";
CM_ SG_ 2148892591 T2U_TMS_EnvTemp_2 "2号TMS环境温度";
CM_ SG_ 2148892591 T2U_TMS_K2_HVRealyState_2 "预留";
CM_ SG_ 2148892591 M2P_TMS_OvrTmpLwFltLvl3_2_31 "2号TMS_制冷模式保护";
CM_ SG_ 2349461137 IsoFault "主MBMU发送给从MBMU绝缘故障";
CM_ SG_ 2349461137 M2M_SUMDATA1_Reserved "主MBMU发送给从MBMU绝缘故障";
CM_ SG_ 2149023633 CRC_M2S_RTC "MBMU到SBMU的对时信息的CRC";
CM_ SG_ 2149023633 RTC_Year "实时时钟年";
CM_ SG_ 2149023633 RTC_Month "实时时钟月";
CM_ SG_ 2149023633 RTC_date "实时时钟日";
CM_ SG_ 2149023633 RTC_Hour "实时时钟时";
CM_ SG_ 2149023633 RTC_minute "实时时钟分";
CM_ SG_ 2149023633 RTC_second "实时时钟秒";
CM_ SG_ 2149023633 RTC_CMD "实时时钟控制指令";
CM_ SG_ 2149023634 CRC_M2S_RTC "MBMU到SBMU的对时信息的CRC";
CM_ SG_ 2149023634 RTC_Year "实时时钟年";
CM_ SG_ 2149023634 RTC_Month "实时时钟月";
CM_ SG_ 2149023634 RTC_date "实时时钟日";
CM_ SG_ 2149023634 RTC_Hour "实时时钟时";
CM_ SG_ 2149023634 RTC_minute "实时时钟分";
CM_ SG_ 2149023634 RTC_second "实时时钟秒";
CM_ SG_ 2149023634 RTC_CMD "实时时钟控制指令";
CM_ SG_ 2149023635 CRC_M2S_RTC "MBMU到SBMU的对时信息的CRC";
CM_ SG_ 2149023635 RTC_Year "实时时钟年";
CM_ SG_ 2149023635 RTC_Month "实时时钟月";
CM_ SG_ 2149023635 RTC_date "实时时钟日";
CM_ SG_ 2149023635 RTC_Hour "实时时钟时";
CM_ SG_ 2149023635 RTC_minute "实时时钟分";
CM_ SG_ 2149023635 RTC_second "实时时钟秒";
CM_ SG_ 2149023635 RTC_CMD "实时时钟控制指令";
CM_ SG_ 2149023636 CRC_M2S_RTC "MBMU到SBMU的对时信息的CRC";
CM_ SG_ 2149023636 RTC_Year "实时时钟年";
CM_ SG_ 2149023636 RTC_Month "实时时钟月";
CM_ SG_ 2149023636 RTC_date "实时时钟日";
CM_ SG_ 2149023636 RTC_Hour "实时时钟时";
CM_ SG_ 2149023636 RTC_minute "实时时钟分";
CM_ SG_ 2149023636 RTC_second "实时时钟秒";
CM_ SG_ 2149023636 RTC_CMD "实时时钟控制指令";
CM_ SG_ 2149023637 CRC_M2S_RTC "MBMU到SBMU的对时信息的CRC";
CM_ SG_ 2149023637 RTC_Year "实时时钟年";
CM_ SG_ 2149023637 RTC_Month "实时时钟月";
CM_ SG_ 2149023637 RTC_date "实时时钟日";
CM_ SG_ 2149023637 RTC_Hour "实时时钟时";
CM_ SG_ 2149023637 RTC_minute "实时时钟分";
CM_ SG_ 2149023637 RTC_second "实时时钟秒";
CM_ SG_ 2149023637 RTC_CMD "实时时钟控制指令";
CM_ SG_ 2149023638 CRC_M2S_RTC "MBMU到SBMU的对时信息的CRC";
CM_ SG_ 2149023638 RTC_Year "实时时钟年";
CM_ SG_ 2149023638 RTC_Month "实时时钟月";
CM_ SG_ 2149023638 RTC_date "实时时钟日";
CM_ SG_ 2149023638 RTC_Hour "实时时钟时";
CM_ SG_ 2149023638 RTC_minute "实时时钟分";
CM_ SG_ 2149023638 RTC_second "实时时钟秒";
CM_ SG_ 2149023638 RTC_CMD "实时时钟控制指令";
CM_ SG_ 2149023639 CRC_M2S_RTC "MBMU到SBMU的对时信息的CRC";
CM_ SG_ 2149023639 RTC_Year "实时时钟年";
CM_ SG_ 2149023639 RTC_Month "实时时钟月";
CM_ SG_ 2149023639 RTC_date "实时时钟日";
CM_ SG_ 2149023639 RTC_Hour "实时时钟时";
CM_ SG_ 2149023639 RTC_minute "实时时钟分";
CM_ SG_ 2149023639 RTC_second "实时时钟秒";
CM_ SG_ 2149023639 RTC_CMD "实时时钟控制指令";
CM_ SG_ 2149023640 CRC_M2S_RTC "MBMU到SBMU的对时信息的CRC";
CM_ SG_ 2149023640 RTC_Year "实时时钟年";
CM_ SG_ 2149023640 RTC_Month "实时时钟月";
CM_ SG_ 2149023640 RTC_date "实时时钟日";
CM_ SG_ 2149023640 RTC_Hour "实时时钟时";
CM_ SG_ 2149023640 RTC_minute "实时时钟分";
CM_ SG_ 2149023640 RTC_second "实时时钟秒";
CM_ SG_ 2149023640 RTC_CMD "实时时钟控制指令";
CM_ SG_ 2149023641 CRC_M2S_RTC "MBMU到SBMU的对时信息的CRC";
CM_ SG_ 2149023641 RTC_Year "实时时钟年";
CM_ SG_ 2149023641 RTC_Month "实时时钟月";
CM_ SG_ 2149023641 RTC_date "实时时钟日";
CM_ SG_ 2149023641 RTC_Hour "实时时钟时";
CM_ SG_ 2149023641 RTC_minute "实时时钟分";
CM_ SG_ 2149023641 RTC_second "实时时钟秒";
CM_ SG_ 2149023641 RTC_CMD "实时时钟控制指令";
CM_ SG_ 2149023642 CRC_M2S_RTC "MBMU到SBMU的对时信息的CRC";
CM_ SG_ 2149023642 RTC_Year "实时时钟年";
CM_ SG_ 2149023642 RTC_Month "实时时钟月";
CM_ SG_ 2149023642 RTC_date "实时时钟日";
CM_ SG_ 2149023642 RTC_Hour "实时时钟时";
CM_ SG_ 2149023642 RTC_minute "实时时钟分";
CM_ SG_ 2149023642 RTC_second "实时时钟秒";
CM_ SG_ 2149023642 RTC_CMD "实时时钟控制指令";
CM_ SG_ 2149023643 CRC_M2S_RTC "MBMU到SBMU的对时信息的CRC";
CM_ SG_ 2149023643 RTC_Year "实时时钟年";
CM_ SG_ 2149023643 RTC_Month "实时时钟月";
CM_ SG_ 2149023643 RTC_date "实时时钟日";
CM_ SG_ 2149023643 RTC_Hour "实时时钟时";
CM_ SG_ 2149023643 RTC_minute "实时时钟分";
CM_ SG_ 2149023643 RTC_second "实时时钟秒";
CM_ SG_ 2149023643 RTC_CMD "实时时钟控制指令";
CM_ SG_ 2149023644 CRC_M2S_RTC "MBMU到SBMU的对时信息的CRC";
CM_ SG_ 2149023644 RTC_Year "实时时钟年";
CM_ SG_ 2149023644 RTC_Month "实时时钟月";
CM_ SG_ 2149023644 RTC_date "实时时钟日";
CM_ SG_ 2149023644 RTC_Hour "实时时钟时";
CM_ SG_ 2149023644 RTC_minute "实时时钟分";
CM_ SG_ 2149023644 RTC_second "实时时钟秒";
CM_ SG_ 2149023644 RTC_CMD "实时时钟控制指令";
CM_ SG_ 2149023645 CRC_M2S_RTC "MBMU到SBMU的对时信息的CRC";
CM_ SG_ 2149023645 RTC_Year "实时时钟年";
CM_ SG_ 2149023645 RTC_Month "实时时钟月";
CM_ SG_ 2149023645 RTC_date "实时时钟日";
CM_ SG_ 2149023645 RTC_Hour "实时时钟时";
CM_ SG_ 2149023645 RTC_minute "实时时钟分";
CM_ SG_ 2149023645 RTC_second "实时时钟秒";
CM_ SG_ 2149023645 RTC_CMD "实时时钟控制指令";
CM_ SG_ 2149023646 CRC_M2S_RTC "MBMU到SBMU的对时信息的CRC";
CM_ SG_ 2149023646 RTC_Year "实时时钟年";
CM_ SG_ 2149023646 RTC_Month "实时时钟月";
CM_ SG_ 2149023646 RTC_date "实时时钟日";
CM_ SG_ 2149023646 RTC_Hour "实时时钟时";
CM_ SG_ 2149023646 RTC_minute "实时时钟分";
CM_ SG_ 2149023646 RTC_second "实时时钟秒";
CM_ SG_ 2149023646 RTC_CMD "实时时钟控制指令";
CM_ SG_ 2149023647 CRC_M2S_RTC "MBMU到SBMU的对时信息的CRC";
CM_ SG_ 2149023647 RTC_Year "实时时钟年";
CM_ SG_ 2149023647 RTC_Month "实时时钟月";
CM_ SG_ 2149023647 RTC_date "实时时钟日";
CM_ SG_ 2149023647 RTC_Hour "实时时钟时";
CM_ SG_ 2149023647 RTC_minute "实时时钟分";
CM_ SG_ 2149023647 RTC_second "实时时钟秒";
CM_ SG_ 2149023647 RTC_CMD "实时时钟控制指令";
CM_ SG_ 2149023648 CRC_M2S_RTC "MBMU到SBMU的对时信息的CRC";
CM_ SG_ 2149023648 RTC_Year "实时时钟年";
CM_ SG_ 2149023648 RTC_Month "实时时钟月";
CM_ SG_ 2149023648 RTC_date "实时时钟日";
CM_ SG_ 2149023648 RTC_Hour "实时时钟时";
CM_ SG_ 2149023648 RTC_minute "实时时钟分";
CM_ SG_ 2149023648 RTC_second "实时时钟秒";
CM_ SG_ 2149023648 RTC_CMD "实时时钟控制指令";
CM_ SG_ 2149023649 CRC_M2S_RTC "MBMU到SBMU的对时信息的CRC";
CM_ SG_ 2149023649 RTC_Year "实时时钟年";
CM_ SG_ 2149023649 RTC_Month "实时时钟月";
CM_ SG_ 2149023649 RTC_date "实时时钟日";
CM_ SG_ 2149023649 RTC_Hour "实时时钟时";
CM_ SG_ 2149023649 RTC_minute "实时时钟分";
CM_ SG_ 2149023649 RTC_second "实时时钟秒";
CM_ SG_ 2149023649 RTC_CMD "实时时钟控制指令";
CM_ SG_ 2149023650 CRC_M2S_RTC "MBMU到SBMU的对时信息的CRC";
CM_ SG_ 2149023650 RTC_Year "实时时钟年";
CM_ SG_ 2149023650 RTC_Month "实时时钟月";
CM_ SG_ 2149023650 RTC_date "实时时钟日";
CM_ SG_ 2149023650 RTC_Hour "实时时钟时";
CM_ SG_ 2149023650 RTC_minute "实时时钟分";
CM_ SG_ 2149023650 RTC_second "实时时钟秒";
CM_ SG_ 2149023650 RTC_CMD "实时时钟控制指令";
CM_ SG_ 2149023651 CRC_M2S_RTC "MBMU到SBMU的对时信息的CRC";
CM_ SG_ 2149023651 RTC_Year "实时时钟年";
CM_ SG_ 2149023651 RTC_Month "实时时钟月";
CM_ SG_ 2149023651 RTC_date "实时时钟日";
CM_ SG_ 2149023651 RTC_Hour "实时时钟时";
CM_ SG_ 2149023651 RTC_minute "实时时钟分";
CM_ SG_ 2149023651 RTC_second "实时时钟秒";
CM_ SG_ 2149023651 RTC_CMD "实时时钟控制指令";
CM_ SG_ 2149023652 CRC_M2S_RTC "MBMU到SBMU的对时信息的CRC";
CM_ SG_ 2149023652 RTC_Year "实时时钟年";
CM_ SG_ 2149023652 RTC_Month "实时时钟月";
CM_ SG_ 2149023652 RTC_date "实时时钟日";
CM_ SG_ 2149023652 RTC_Hour "实时时钟时";
CM_ SG_ 2149023652 RTC_minute "实时时钟分";
CM_ SG_ 2149023652 RTC_second "实时时钟秒";
CM_ SG_ 2149023652 RTC_CMD "实时时钟控制指令";
CM_ SG_ 2149023653 CRC_M2S_RTC "MBMU到SBMU的对时信息的CRC";
CM_ SG_ 2149023653 RTC_Year "实时时钟年";
CM_ SG_ 2149023653 RTC_Month "实时时钟月";
CM_ SG_ 2149023653 RTC_date "实时时钟日";
CM_ SG_ 2149023653 RTC_Hour "实时时钟时";
CM_ SG_ 2149023653 RTC_minute "实时时钟分";
CM_ SG_ 2149023653 RTC_second "实时时钟秒";
CM_ SG_ 2149023653 RTC_CMD "实时时钟控制指令";
CM_ SG_ 2149023654 CRC_M2S_RTC "MBMU到SBMU的对时信息的CRC";
CM_ SG_ 2149023654 RTC_Year "实时时钟年";
CM_ SG_ 2149023654 RTC_Month "实时时钟月";
CM_ SG_ 2149023654 RTC_date "实时时钟日";
CM_ SG_ 2149023654 RTC_Hour "实时时钟时";
CM_ SG_ 2149023654 RTC_minute "实时时钟分";
CM_ SG_ 2149023654 RTC_second "实时时钟秒";
CM_ SG_ 2149023654 RTC_CMD "实时时钟控制指令";
CM_ SG_ 2149023655 CRC_M2S_RTC "MBMU到SBMU的对时信息的CRC";
CM_ SG_ 2149023655 RTC_Year "实时时钟年";
CM_ SG_ 2149023655 RTC_Month "实时时钟月";
CM_ SG_ 2149023655 RTC_date "实时时钟日";
CM_ SG_ 2149023655 RTC_Hour "实时时钟时";
CM_ SG_ 2149023655 RTC_minute "实时时钟分";
CM_ SG_ 2149023655 RTC_second "实时时钟秒";
CM_ SG_ 2149023655 RTC_CMD "实时时钟控制指令";
CM_ SG_ 2149023656 CRC_M2S_RTC "MBMU到SBMU的对时信息的CRC";
CM_ SG_ 2149023656 RTC_Year "实时时钟年";
CM_ SG_ 2149023656 RTC_Month "实时时钟月";
CM_ SG_ 2149023656 RTC_date "实时时钟日";
CM_ SG_ 2149023656 RTC_Hour "实时时钟时";
CM_ SG_ 2149023656 RTC_minute "实时时钟分";
CM_ SG_ 2149023656 RTC_second "实时时钟秒";
CM_ SG_ 2149023656 RTC_CMD "实时时钟控制指令";
CM_ SG_ 2149023657 CRC_M2S_RTC "MBMU到SBMU的对时信息的CRC";
CM_ SG_ 2149023657 RTC_Year "实时时钟年";
CM_ SG_ 2149023657 RTC_Month "实时时钟月";
CM_ SG_ 2149023657 RTC_date "实时时钟日";
CM_ SG_ 2149023657 RTC_Hour "实时时钟时";
CM_ SG_ 2149023657 RTC_minute "实时时钟分";
CM_ SG_ 2149023657 RTC_second "实时时钟秒";
CM_ SG_ 2149023657 RTC_CMD "实时时钟控制指令";
CM_ SG_ 2149023658 CRC_M2S_RTC "MBMU到SBMU的对时信息的CRC";
CM_ SG_ 2149023658 RTC_Year "实时时钟年";
CM_ SG_ 2149023658 RTC_Month "实时时钟月";
CM_ SG_ 2149023658 RTC_date "实时时钟日";
CM_ SG_ 2149023658 RTC_Hour "实时时钟时";
CM_ SG_ 2149023658 RTC_minute "实时时钟分";
CM_ SG_ 2149023658 RTC_second "实时时钟秒";
CM_ SG_ 2149023658 RTC_CMD "实时时钟控制指令";
CM_ SG_ 2149023659 CRC_M2S_RTC "MBMU到SBMU的对时信息的CRC";
CM_ SG_ 2149023659 RTC_Year "实时时钟年";
CM_ SG_ 2149023659 RTC_Month "实时时钟月";
CM_ SG_ 2149023659 RTC_date "实时时钟日";
CM_ SG_ 2149023659 RTC_Hour "实时时钟时";
CM_ SG_ 2149023659 RTC_minute "实时时钟分";
CM_ SG_ 2149023659 RTC_second "实时时钟秒";
CM_ SG_ 2149023659 RTC_CMD "实时时钟控制指令";
CM_ SG_ 2149023660 CRC_M2S_RTC "MBMU到SBMU的对时信息的CRC";
CM_ SG_ 2149023660 RTC_Year "实时时钟年";
CM_ SG_ 2149023660 RTC_Month "实时时钟月";
CM_ SG_ 2149023660 RTC_date "实时时钟日";
CM_ SG_ 2149023660 RTC_Hour "实时时钟时";
CM_ SG_ 2149023660 RTC_minute "实时时钟分";
CM_ SG_ 2149023660 RTC_second "实时时钟秒";
CM_ SG_ 2149023660 RTC_CMD "实时时钟控制指令";
CM_ SG_ 2149023661 CRC_M2S_RTC "MBMU到SBMU的对时信息的CRC";
CM_ SG_ 2149023661 RTC_Year "实时时钟年";
CM_ SG_ 2149023661 RTC_Month "实时时钟月";
CM_ SG_ 2149023661 RTC_date "实时时钟日";
CM_ SG_ 2149023661 RTC_Hour "实时时钟时";
CM_ SG_ 2149023661 RTC_minute "实时时钟分";
CM_ SG_ 2149023661 RTC_second "实时时钟秒";
CM_ SG_ 2149023661 RTC_CMD "实时时钟控制指令";
CM_ SG_ 2149023662 CRC_M2S_RTC "MBMU到SBMU的对时信息的CRC";
CM_ SG_ 2149023662 RTC_Year "实时时钟年";
CM_ SG_ 2149023662 RTC_Month "实时时钟月";
CM_ SG_ 2149023662 RTC_date "实时时钟日";
CM_ SG_ 2149023662 RTC_Hour "实时时钟时";
CM_ SG_ 2149023662 RTC_minute "实时时钟分";
CM_ SG_ 2149023662 RTC_second "实时时钟秒";
CM_ SG_ 2149023662 RTC_CMD "实时时钟控制指令";
CM_ SG_ 2149023663 CRC_M2S_RTC "MBMU到SBMU的对时信息的CRC";
CM_ SG_ 2149023663 RTC_Year "实时时钟年";
CM_ SG_ 2149023663 RTC_Month "实时时钟月";
CM_ SG_ 2149023663 RTC_date "实时时钟日";
CM_ SG_ 2149023663 RTC_Hour "实时时钟时";
CM_ SG_ 2149023663 RTC_minute "实时时钟分";
CM_ SG_ 2149023663 RTC_second "实时时钟秒";
CM_ SG_ 2149023663 RTC_CMD "实时时钟控制指令";
CM_ SG_ 2433198830 P2M_Cfg6_MBMU_data1 "PC的控制上下高压命令      ";
CM_ SG_ 2433198830 P2M_Cfg6_MBMU_data2 "PC写入数据           ";
CM_ SG_ 2433198830 P2M_Cfg6_MBMU_data3 "根据功能码定义和解析数据1";
CM_ SG_ 2433198830 P2M_Cfg6_MBMU_data4 "根据功能码定义和解析数据2";
CM_ SG_ 2433198830 P2M_Cfg6_MBMU_data5 "根据功能码定义和解析数据3";
CM_ SG_ 2433198830 P2M_Cfg6_MBMU_data6 "根据功能码定义和解析数据4";
CM_ SG_ 2433198830 P2M_Cfg6_MBMU_data7 "根据功能码定义和解析数据5";
CM_ SG_ 2433198830 P2M_Cfg6_MBMU_data8 "根据功能码定义和解析数据6";
CM_ SG_ 2417880641 S2P_Response_Byte1_01 "新增功能使用：";
CM_ SG_ 2417880641 S2P_Response_Byte2_01 "新增功能使用： 功能编码，根据功能定义具含义";
CM_ SG_ 2417880641 S2P_Response_Byte3_01 "根据功能码定义和解析数据1";
CM_ SG_ 2417880641 S2P_Response_Byte4_01 "根据功能码定义和解析数据2";
CM_ SG_ 2417880641 S2P_Response_Byte5_01 "根据功能码定义和解析数据3";
CM_ SG_ 2417880641 S2P_Response_Byte6_01 "根据功能码定义和解析数据4";
CM_ SG_ 2417880641 S2P_Response_Byte7_01 "根据功能码定义和解析数据5";
CM_ SG_ 2417880641 S2P_Response_Byte8_01 "根据功能码定义和解析数据6";
CM_ SG_ 2417880642 S2P_Response_Byte1_02 "新增功能使用：";
CM_ SG_ 2417880642 S2P_Response_Byte2_02 "新增功能使用： 功能编码，根据功能定义具含义";
CM_ SG_ 2417880642 S2P_Response_Byte3_02 "根据功能码定义和解析数据1";
CM_ SG_ 2417880642 S2P_Response_Byte4_02 "根据功能码定义和解析数据2";
CM_ SG_ 2417880642 S2P_Response_Byte5_02 "根据功能码定义和解析数据3";
CM_ SG_ 2417880642 S2P_Response_Byte6_02 "根据功能码定义和解析数据4";
CM_ SG_ 2417880642 S2P_Response_Byte7_02 "根据功能码定义和解析数据5";
CM_ SG_ 2417880642 S2P_Response_Byte8_02 "根据功能码定义和解析数据6";
CM_ SG_ 2417880643 S2P_Response_Byte1_03 "新增功能使用：";
CM_ SG_ 2417880643 S2P_Response_Byte2_03 "新增功能使用： 功能编码，根据功能定义具含义";
CM_ SG_ 2417880643 S2P_Response_Byte3_03 "根据功能码定义和解析数据1";
CM_ SG_ 2417880643 S2P_Response_Byte4_03 "根据功能码定义和解析数据2";
CM_ SG_ 2417880643 S2P_Response_Byte5_03 "根据功能码定义和解析数据3";
CM_ SG_ 2417880643 S2P_Response_Byte6_03 "根据功能码定义和解析数据4";
CM_ SG_ 2417880643 S2P_Response_Byte7_03 "根据功能码定义和解析数据5";
CM_ SG_ 2417880643 S2P_Response_Byte8_03 "根据功能码定义和解析数据6";
CM_ SG_ 2417880644 S2P_Response_Byte1_04 "新增功能使用：";
CM_ SG_ 2417880644 S2P_Response_Byte2_04 "新增功能使用： 功能编码，根据功能定义具含义";
CM_ SG_ 2417880644 S2P_Response_Byte3_04 "根据功能码定义和解析数据1";
CM_ SG_ 2417880644 S2P_Response_Byte4_04 "根据功能码定义和解析数据2";
CM_ SG_ 2417880644 S2P_Response_Byte5_04 "根据功能码定义和解析数据3";
CM_ SG_ 2417880644 S2P_Response_Byte6_04 "根据功能码定义和解析数据4";
CM_ SG_ 2417880644 S2P_Response_Byte7_04 "根据功能码定义和解析数据5";
CM_ SG_ 2417880644 S2P_Response_Byte8_04 "根据功能码定义和解析数据6";
CM_ SG_ 2417880645 S2P_Response_Byte1_05 "新增功能使用：";
CM_ SG_ 2417880645 S2P_Response_Byte2_05 "新增功能使用： 功能编码，根据功能定义具含义";
CM_ SG_ 2417880645 S2P_Response_Byte3_05 "根据功能码定义和解析数据1";
CM_ SG_ 2417880645 S2P_Response_Byte4_05 "根据功能码定义和解析数据2";
CM_ SG_ 2417880645 S2P_Response_Byte5_05 "根据功能码定义和解析数据3";
CM_ SG_ 2417880645 S2P_Response_Byte6_05 "根据功能码定义和解析数据4";
CM_ SG_ 2417880645 S2P_Response_Byte7_05 "根据功能码定义和解析数据5";
CM_ SG_ 2417880645 S2P_Response_Byte8_05 "根据功能码定义和解析数据6";
CM_ SG_ 2417880646 S2P_Response_Byte1_06 "新增功能使用：";
CM_ SG_ 2417880646 S2P_Response_Byte2_06 "新增功能使用： 功能编码，根据功能定义具含义";
CM_ SG_ 2417880646 S2P_Response_Byte3_06 "根据功能码定义和解析数据1";
CM_ SG_ 2417880646 S2P_Response_Byte4_06 "根据功能码定义和解析数据2";
CM_ SG_ 2417880646 S2P_Response_Byte5_06 "根据功能码定义和解析数据3";
CM_ SG_ 2417880646 S2P_Response_Byte6_06 "根据功能码定义和解析数据4";
CM_ SG_ 2417880646 S2P_Response_Byte7_06 "根据功能码定义和解析数据5";
CM_ SG_ 2417880646 S2P_Response_Byte8_06 "根据功能码定义和解析数据6";
CM_ SG_ 2417880647 S2P_Response_Byte1_07 "新增功能使用：";
CM_ SG_ 2417880647 S2P_Response_Byte2_07 "新增功能使用： 功能编码，根据功能定义具含义";
CM_ SG_ 2417880647 S2P_Response_Byte3_07 "根据功能码定义和解析数据1";
CM_ SG_ 2417880647 S2P_Response_Byte4_07 "根据功能码定义和解析数据2";
CM_ SG_ 2417880647 S2P_Response_Byte5_07 "根据功能码定义和解析数据3";
CM_ SG_ 2417880647 S2P_Response_Byte6_07 "根据功能码定义和解析数据4";
CM_ SG_ 2417880647 S2P_Response_Byte7_07 "根据功能码定义和解析数据5";
CM_ SG_ 2417880647 S2P_Response_Byte8_07 "根据功能码定义和解析数据6";
CM_ SG_ 2417880648 S2P_Response_Byte1_08 "新增功能使用：";
CM_ SG_ 2417880648 S2P_Response_Byte2_08 "新增功能使用： 功能编码，根据功能定义具含义";
CM_ SG_ 2417880648 S2P_Response_Byte3_08 "根据功能码定义和解析数据1";
CM_ SG_ 2417880648 S2P_Response_Byte4_08 "根据功能码定义和解析数据2";
CM_ SG_ 2417880648 S2P_Response_Byte5_08 "根据功能码定义和解析数据3";
CM_ SG_ 2417880648 S2P_Response_Byte6_08 "根据功能码定义和解析数据4";
CM_ SG_ 2417880648 S2P_Response_Byte7_08 "根据功能码定义和解析数据5";
CM_ SG_ 2417880648 S2P_Response_Byte8_08 "根据功能码定义和解析数据6";
CM_ SG_ 2417880649 S2P_Response_Byte1_09 "新增功能使用：";
CM_ SG_ 2417880649 S2P_Response_Byte2_09 "新增功能使用： 功能编码，根据功能定义具含义";
CM_ SG_ 2417880649 S2P_Response_Byte3_09 "根据功能码定义和解析数据1";
CM_ SG_ 2417880649 S2P_Response_Byte4_09 "根据功能码定义和解析数据2";
CM_ SG_ 2417880649 S2P_Response_Byte5_09 "根据功能码定义和解析数据3";
CM_ SG_ 2417880649 S2P_Response_Byte6_09 "根据功能码定义和解析数据4";
CM_ SG_ 2417880649 S2P_Response_Byte7_09 "根据功能码定义和解析数据5";
CM_ SG_ 2417880649 S2P_Response_Byte8_09 "根据功能码定义和解析数据6";
CM_ SG_ 2417880650 S2P_Response_Byte1_10 "新增功能使用：";
CM_ SG_ 2417880650 S2P_Response_Byte2_10 "新增功能使用： 功能编码，根据功能定义具含义";
CM_ SG_ 2417880650 S2P_Response_Byte3_10 "根据功能码定义和解析数据1";
CM_ SG_ 2417880650 S2P_Response_Byte4_10 "根据功能码定义和解析数据2";
CM_ SG_ 2417880650 S2P_Response_Byte5_10 "根据功能码定义和解析数据3";
CM_ SG_ 2417880650 S2P_Response_Byte6_10 "根据功能码定义和解析数据4";
CM_ SG_ 2417880650 S2P_Response_Byte7_10 "根据功能码定义和解析数据5";
CM_ SG_ 2417880650 S2P_Response_Byte8_10 "根据功能码定义和解析数据6";
CM_ SG_ 2417880651 S2P_Response_Byte1_11 "新增功能使用：";
CM_ SG_ 2417880651 S2P_Response_Byte2_11 "新增功能使用： 功能编码，根据功能定义具含义";
CM_ SG_ 2417880651 S2P_Response_Byte3_11 "根据功能码定义和解析数据1";
CM_ SG_ 2417880651 S2P_Response_Byte4_11 "根据功能码定义和解析数据2";
CM_ SG_ 2417880651 S2P_Response_Byte5_11 "根据功能码定义和解析数据3";
CM_ SG_ 2417880651 S2P_Response_Byte6_11 "根据功能码定义和解析数据4";
CM_ SG_ 2417880651 S2P_Response_Byte7_11 "根据功能码定义和解析数据5";
CM_ SG_ 2417880651 S2P_Response_Byte8_11 "根据功能码定义和解析数据6";
CM_ SG_ 2417880652 S2P_Response_Byte1_12 "新增功能使用：";
CM_ SG_ 2417880652 S2P_Response_Byte2_12 "新增功能使用： 功能编码，根据功能定义具含义";
CM_ SG_ 2417880652 S2P_Response_Byte3_12 "根据功能码定义和解析数据1";
CM_ SG_ 2417880652 S2P_Response_Byte4_12 "根据功能码定义和解析数据2";
CM_ SG_ 2417880652 S2P_Response_Byte5_12 "根据功能码定义和解析数据3";
CM_ SG_ 2417880652 S2P_Response_Byte6_12 "根据功能码定义和解析数据4";
CM_ SG_ 2417880652 S2P_Response_Byte7_12 "根据功能码定义和解析数据5";
CM_ SG_ 2417880652 S2P_Response_Byte8_12 "根据功能码定义和解析数据6";
CM_ SG_ 2417880653 S2P_Response_Byte1_13 "新增功能使用：";
CM_ SG_ 2417880653 S2P_Response_Byte2_13 "新增功能使用： 功能编码，根据功能定义具含义";
CM_ SG_ 2417880653 S2P_Response_Byte3_13 "根据功能码定义和解析数据1";
CM_ SG_ 2417880653 S2P_Response_Byte4_13 "根据功能码定义和解析数据2";
CM_ SG_ 2417880653 S2P_Response_Byte5_13 "根据功能码定义和解析数据3";
CM_ SG_ 2417880653 S2P_Response_Byte6_13 "根据功能码定义和解析数据4";
CM_ SG_ 2417880653 S2P_Response_Byte7_13 "根据功能码定义和解析数据5";
CM_ SG_ 2417880653 S2P_Response_Byte8_13 "根据功能码定义和解析数据6";
CM_ SG_ 2417880654 S2P_Response_Byte1_14 "新增功能使用：";
CM_ SG_ 2417880654 S2P_Response_Byte2_14 "新增功能使用： 功能编码，根据功能定义具含义";
CM_ SG_ 2417880654 S2P_Response_Byte3_14 "根据功能码定义和解析数据1";
CM_ SG_ 2417880654 S2P_Response_Byte4_14 "根据功能码定义和解析数据2";
CM_ SG_ 2417880654 S2P_Response_Byte5_14 "根据功能码定义和解析数据3";
CM_ SG_ 2417880654 S2P_Response_Byte6_14 "根据功能码定义和解析数据4";
CM_ SG_ 2417880654 S2P_Response_Byte7_14 "根据功能码定义和解析数据5";
CM_ SG_ 2417880654 S2P_Response_Byte8_14 "根据功能码定义和解析数据6";
CM_ SG_ 2417880655 S2P_Response_Byte1_15 "新增功能使用：";
CM_ SG_ 2417880655 S2P_Response_Byte2_15 "新增功能使用： 功能编码，根据功能定义具含义";
CM_ SG_ 2417880655 S2P_Response_Byte3_15 "根据功能码定义和解析数据1";
CM_ SG_ 2417880655 S2P_Response_Byte4_15 "根据功能码定义和解析数据2";
CM_ SG_ 2417880655 S2P_Response_Byte5_15 "根据功能码定义和解析数据3";
CM_ SG_ 2417880655 S2P_Response_Byte6_15 "根据功能码定义和解析数据4";
CM_ SG_ 2417880655 S2P_Response_Byte7_15 "根据功能码定义和解析数据5";
CM_ SG_ 2417880655 S2P_Response_Byte8_15 "根据功能码定义和解析数据6";
CM_ SG_ 2417880656 S2P_Response_Byte1_16 "新增功能使用：";
CM_ SG_ 2417880656 S2P_Response_Byte2_16 "新增功能使用： 功能编码，根据功能定义具含义";
CM_ SG_ 2417880656 S2P_Response_Byte3_16 "根据功能码定义和解析数据1";
CM_ SG_ 2417880656 S2P_Response_Byte4_16 "根据功能码定义和解析数据2";
CM_ SG_ 2417880656 S2P_Response_Byte5_16 "根据功能码定义和解析数据3";
CM_ SG_ 2417880656 S2P_Response_Byte6_16 "根据功能码定义和解析数据4";
CM_ SG_ 2417880656 S2P_Response_Byte7_16 "根据功能码定义和解析数据5";
CM_ SG_ 2417880656 S2P_Response_Byte8_16 "根据功能码定义和解析数据6";
CM_ SG_ 2417880657 S2P_Response_Byte1_17 "新增功能使用：";
CM_ SG_ 2417880657 S2P_Response_Byte2_17 "新增功能使用： 功能编码，根据功能定义具含义";
CM_ SG_ 2417880657 S2P_Response_Byte3_17 "根据功能码定义和解析数据1";
CM_ SG_ 2417880657 S2P_Response_Byte4_17 "根据功能码定义和解析数据2";
CM_ SG_ 2417880657 S2P_Response_Byte5_17 "根据功能码定义和解析数据3";
CM_ SG_ 2417880657 S2P_Response_Byte6_17 "根据功能码定义和解析数据4";
CM_ SG_ 2417880657 S2P_Response_Byte7_17 "根据功能码定义和解析数据5";
CM_ SG_ 2417880657 S2P_Response_Byte8_17 "根据功能码定义和解析数据6";
CM_ SG_ 2417880658 S2P_Response_Byte1_18 "新增功能使用：";
CM_ SG_ 2417880658 S2P_Response_Byte2_18 "新增功能使用： 功能编码，根据功能定义具含义";
CM_ SG_ 2417880658 S2P_Response_Byte3_18 "根据功能码定义和解析数据1";
CM_ SG_ 2417880658 S2P_Response_Byte4_18 "根据功能码定义和解析数据2";
CM_ SG_ 2417880658 S2P_Response_Byte5_18 "根据功能码定义和解析数据3";
CM_ SG_ 2417880658 S2P_Response_Byte6_18 "根据功能码定义和解析数据4";
CM_ SG_ 2417880658 S2P_Response_Byte7_18 "根据功能码定义和解析数据5";
CM_ SG_ 2417880658 S2P_Response_Byte8_18 "根据功能码定义和解析数据6";
CM_ SG_ 2417880659 S2P_Response_Byte1_19 "新增功能使用：";
CM_ SG_ 2417880659 S2P_Response_Byte2_19 "新增功能使用： 功能编码，根据功能定义具含义";
CM_ SG_ 2417880659 S2P_Response_Byte3_19 "根据功能码定义和解析数据1";
CM_ SG_ 2417880659 S2P_Response_Byte4_19 "根据功能码定义和解析数据2";
CM_ SG_ 2417880659 S2P_Response_Byte5_19 "根据功能码定义和解析数据3";
CM_ SG_ 2417880659 S2P_Response_Byte6_19 "根据功能码定义和解析数据4";
CM_ SG_ 2417880659 S2P_Response_Byte7_19 "根据功能码定义和解析数据5";
CM_ SG_ 2417880659 S2P_Response_Byte8_19 "根据功能码定义和解析数据6";
CM_ SG_ 2417880660 S2P_Response_Byte1_20 "新增功能使用：";
CM_ SG_ 2417880660 S2P_Response_Byte2_20 "新增功能使用： 功能编码，根据功能定义具含义";
CM_ SG_ 2417880660 S2P_Response_Byte3_20 "根据功能码定义和解析数据1";
CM_ SG_ 2417880660 S2P_Response_Byte4_20 "根据功能码定义和解析数据2";
CM_ SG_ 2417880660 S2P_Response_Byte5_20 "根据功能码定义和解析数据3";
CM_ SG_ 2417880660 S2P_Response_Byte6_20 "根据功能码定义和解析数据4";
CM_ SG_ 2417880660 S2P_Response_Byte7_20 "根据功能码定义和解析数据5";
CM_ SG_ 2417880660 S2P_Response_Byte8_20 "根据功能码定义和解析数据6";
CM_ SG_ 2417880661 S2P_Response_Byte1_21 "新增功能使用：";
CM_ SG_ 2417880661 S2P_Response_Byte2_21 "新增功能使用： 功能编码，根据功能定义具含义";
CM_ SG_ 2417880661 S2P_Response_Byte3_21 "根据功能码定义和解析数据1";
CM_ SG_ 2417880661 S2P_Response_Byte4_21 "根据功能码定义和解析数据2";
CM_ SG_ 2417880661 S2P_Response_Byte5_21 "根据功能码定义和解析数据3";
CM_ SG_ 2417880661 S2P_Response_Byte6_21 "根据功能码定义和解析数据4";
CM_ SG_ 2417880661 S2P_Response_Byte7_21 "根据功能码定义和解析数据5";
CM_ SG_ 2417880661 S2P_Response_Byte8_21 "根据功能码定义和解析数据6";
CM_ SG_ 2417880662 S2P_Response_Byte1_22 "新增功能使用：";
CM_ SG_ 2417880662 S2P_Response_Byte2_22 "新增功能使用： 功能编码，根据功能定义具含义";
CM_ SG_ 2417880662 S2P_Response_Byte3_22 "根据功能码定义和解析数据1";
CM_ SG_ 2417880662 S2P_Response_Byte4_22 "根据功能码定义和解析数据2";
CM_ SG_ 2417880662 S2P_Response_Byte5_22 "根据功能码定义和解析数据3";
CM_ SG_ 2417880662 S2P_Response_Byte6_22 "根据功能码定义和解析数据4";
CM_ SG_ 2417880662 S2P_Response_Byte7_22 "根据功能码定义和解析数据5";
CM_ SG_ 2417880662 S2P_Response_Byte8_22 "根据功能码定义和解析数据6";
CM_ SG_ 2417880663 S2P_Response_Byte1_23 "新增功能使用：";
CM_ SG_ 2417880663 S2P_Response_Byte2_23 "新增功能使用： 功能编码，根据功能定义具含义";
CM_ SG_ 2417880663 S2P_Response_Byte3_23 "根据功能码定义和解析数据1";
CM_ SG_ 2417880663 S2P_Response_Byte4_23 "根据功能码定义和解析数据2";
CM_ SG_ 2417880663 S2P_Response_Byte5_23 "根据功能码定义和解析数据3";
CM_ SG_ 2417880663 S2P_Response_Byte6_23 "根据功能码定义和解析数据4";
CM_ SG_ 2417880663 S2P_Response_Byte7_23 "根据功能码定义和解析数据5";
CM_ SG_ 2417880663 S2P_Response_Byte8_23 "根据功能码定义和解析数据6";
CM_ SG_ 2417880664 S2P_Response_Byte1_24 "新增功能使用：";
CM_ SG_ 2417880664 S2P_Response_Byte2_24 "新增功能使用： 功能编码，根据功能定义具含义";
CM_ SG_ 2417880664 S2P_Response_Byte3_24 "根据功能码定义和解析数据1";
CM_ SG_ 2417880664 S2P_Response_Byte4_24 "根据功能码定义和解析数据2";
CM_ SG_ 2417880664 S2P_Response_Byte5_24 "根据功能码定义和解析数据3";
CM_ SG_ 2417880664 S2P_Response_Byte6_24 "根据功能码定义和解析数据4";
CM_ SG_ 2417880664 S2P_Response_Byte7_24 "根据功能码定义和解析数据5";
CM_ SG_ 2417880664 S2P_Response_Byte8_24 "根据功能码定义和解析数据6";
CM_ SG_ 2417880665 S2P_Response_Byte1_25 "新增功能使用：";
CM_ SG_ 2417880665 S2P_Response_Byte2_25 "新增功能使用： 功能编码，根据功能定义具含义";
CM_ SG_ 2417880665 S2P_Response_Byte3_25 "根据功能码定义和解析数据1";
CM_ SG_ 2417880665 S2P_Response_Byte4_25 "根据功能码定义和解析数据2";
CM_ SG_ 2417880665 S2P_Response_Byte5_25 "根据功能码定义和解析数据3";
CM_ SG_ 2417880665 S2P_Response_Byte6_25 "根据功能码定义和解析数据4";
CM_ SG_ 2417880665 S2P_Response_Byte7_25 "根据功能码定义和解析数据5";
CM_ SG_ 2417880665 S2P_Response_Byte8_25 "根据功能码定义和解析数据6";
CM_ SG_ 2417880666 S2P_Response_Byte1_26 "新增功能使用：";
CM_ SG_ 2417880666 S2P_Response_Byte2_26 "新增功能使用： 功能编码，根据功能定义具含义";
CM_ SG_ 2417880666 S2P_Response_Byte3_26 "根据功能码定义和解析数据1";
CM_ SG_ 2417880666 S2P_Response_Byte4_26 "根据功能码定义和解析数据2";
CM_ SG_ 2417880666 S2P_Response_Byte5_26 "根据功能码定义和解析数据3";
CM_ SG_ 2417880666 S2P_Response_Byte6_26 "根据功能码定义和解析数据4";
CM_ SG_ 2417880666 S2P_Response_Byte7_26 "根据功能码定义和解析数据5";
CM_ SG_ 2417880666 S2P_Response_Byte8_26 "根据功能码定义和解析数据6";
CM_ SG_ 2417880667 S2P_Response_Byte1_27 "新增功能使用：";
CM_ SG_ 2417880667 S2P_Response_Byte2_27 "新增功能使用： 功能编码，根据功能定义具含义";
CM_ SG_ 2417880667 S2P_Response_Byte3_27 "根据功能码定义和解析数据1";
CM_ SG_ 2417880667 S2P_Response_Byte4_27 "根据功能码定义和解析数据2";
CM_ SG_ 2417880667 S2P_Response_Byte5_27 "根据功能码定义和解析数据3";
CM_ SG_ 2417880667 S2P_Response_Byte6_27 "根据功能码定义和解析数据4";
CM_ SG_ 2417880667 S2P_Response_Byte7_27 "根据功能码定义和解析数据5";
CM_ SG_ 2417880667 S2P_Response_Byte8_27 "根据功能码定义和解析数据6";
CM_ SG_ 2417880668 S2P_Response_Byte1_28 "新增功能使用：";
CM_ SG_ 2417880668 S2P_Response_Byte2_28 "新增功能使用： 功能编码，根据功能定义具含义";
CM_ SG_ 2417880668 S2P_Response_Byte3_28 "根据功能码定义和解析数据1";
CM_ SG_ 2417880668 S2P_Response_Byte4_28 "根据功能码定义和解析数据2";
CM_ SG_ 2417880668 S2P_Response_Byte5_28 "根据功能码定义和解析数据3";
CM_ SG_ 2417880668 S2P_Response_Byte6_28 "根据功能码定义和解析数据4";
CM_ SG_ 2417880668 S2P_Response_Byte7_28 "根据功能码定义和解析数据5";
CM_ SG_ 2417880668 S2P_Response_Byte8_28 "根据功能码定义和解析数据6";
CM_ SG_ 2417880669 S2P_Response_Byte1_29 "新增功能使用：";
CM_ SG_ 2417880669 S2P_Response_Byte2_29 "新增功能使用： 功能编码，根据功能定义具含义";
CM_ SG_ 2417880669 S2P_Response_Byte3_29 "根据功能码定义和解析数据1";
CM_ SG_ 2417880669 S2P_Response_Byte4_29 "根据功能码定义和解析数据2";
CM_ SG_ 2417880669 S2P_Response_Byte5_29 "根据功能码定义和解析数据3";
CM_ SG_ 2417880669 S2P_Response_Byte6_29 "根据功能码定义和解析数据4";
CM_ SG_ 2417880669 S2P_Response_Byte7_29 "根据功能码定义和解析数据5";
CM_ SG_ 2417880669 S2P_Response_Byte8_29 "根据功能码定义和解析数据6";
CM_ SG_ 2417880670 S2P_Response_Byte1_30 "新增功能使用：";
CM_ SG_ 2417880670 S2P_Response_Byte2_30 "新增功能使用： 功能编码，根据功能定义具含义";
CM_ SG_ 2417880670 S2P_Response_Byte3_30 "根据功能码定义和解析数据1";
CM_ SG_ 2417880670 S2P_Response_Byte4_30 "根据功能码定义和解析数据2";
CM_ SG_ 2417880670 S2P_Response_Byte5_30 "根据功能码定义和解析数据3";
CM_ SG_ 2417880670 S2P_Response_Byte6_30 "根据功能码定义和解析数据4";
CM_ SG_ 2417880670 S2P_Response_Byte7_30 "根据功能码定义和解析数据5";
CM_ SG_ 2417880670 S2P_Response_Byte8_30 "根据功能码定义和解析数据6";
CM_ SG_ 2417880671 S2P_Response_Byte1_31 "新增功能使用：";
CM_ SG_ 2417880671 S2P_Response_Byte2_31 "新增功能使用： 功能编码，根据功能定义具含义";
CM_ SG_ 2417880671 S2P_Response_Byte3_31 "根据功能码定义和解析数据1";
CM_ SG_ 2417880671 S2P_Response_Byte4_31 "根据功能码定义和解析数据2";
CM_ SG_ 2417880671 S2P_Response_Byte5_31 "根据功能码定义和解析数据3";
CM_ SG_ 2417880671 S2P_Response_Byte6_31 "根据功能码定义和解析数据4";
CM_ SG_ 2417880671 S2P_Response_Byte7_31 "根据功能码定义和解析数据5";
CM_ SG_ 2417880671 S2P_Response_Byte8_31 "根据功能码定义和解析数据6";
CM_ SG_ 2417880672 S2P_Response_Byte1_32 "新增功能使用：";
CM_ SG_ 2417880672 S2P_Response_Byte2_32 "新增功能使用： 功能编码，根据功能定义具含义";
CM_ SG_ 2417880672 S2P_Response_Byte3_32 "根据功能码定义和解析数据1";
CM_ SG_ 2417880672 S2P_Response_Byte4_32 "根据功能码定义和解析数据2";
CM_ SG_ 2417880672 S2P_Response_Byte5_32 "根据功能码定义和解析数据3";
CM_ SG_ 2417880672 S2P_Response_Byte6_32 "根据功能码定义和解析数据4";
CM_ SG_ 2417880672 S2P_Response_Byte7_32 "根据功能码定义和解析数据5";
CM_ SG_ 2417880672 S2P_Response_Byte8_32 "根据功能码定义和解析数据6";
CM_ SG_ 2417880673 S2P_Response_Byte1_33 "新增功能使用：";
CM_ SG_ 2417880673 S2P_Response_Byte2_33 "新增功能使用： 功能编码，根据功能定义具含义";
CM_ SG_ 2417880673 S2P_Response_Byte3_33 "根据功能码定义和解析数据1";
CM_ SG_ 2417880673 S2P_Response_Byte4_33 "根据功能码定义和解析数据2";
CM_ SG_ 2417880673 S2P_Response_Byte5_33 "根据功能码定义和解析数据3";
CM_ SG_ 2417880673 S2P_Response_Byte6_33 "根据功能码定义和解析数据4";
CM_ SG_ 2417880673 S2P_Response_Byte7_33 "根据功能码定义和解析数据5";
CM_ SG_ 2417880673 S2P_Response_Byte8_33 "根据功能码定义和解析数据6";
CM_ SG_ 2417880674 S2P_Response_Byte1_34 "新增功能使用：";
CM_ SG_ 2417880674 S2P_Response_Byte2_34 "新增功能使用： 功能编码，根据功能定义具含义";
CM_ SG_ 2417880674 S2P_Response_Byte3_34 "根据功能码定义和解析数据1";
CM_ SG_ 2417880674 S2P_Response_Byte4_34 "根据功能码定义和解析数据2";
CM_ SG_ 2417880674 S2P_Response_Byte5_34 "根据功能码定义和解析数据3";
CM_ SG_ 2417880674 S2P_Response_Byte6_34 "根据功能码定义和解析数据4";
CM_ SG_ 2417880674 S2P_Response_Byte7_34 "根据功能码定义和解析数据5";
CM_ SG_ 2417880674 S2P_Response_Byte8_34 "根据功能码定义和解析数据6";
CM_ SG_ 2417880675 S2P_Response_Byte1_35 "新增功能使用：";
CM_ SG_ 2417880675 S2P_Response_Byte2_35 "新增功能使用： 功能编码，根据功能定义具含义";
CM_ SG_ 2417880675 S2P_Response_Byte3_35 "根据功能码定义和解析数据1";
CM_ SG_ 2417880675 S2P_Response_Byte4_35 "根据功能码定义和解析数据2";
CM_ SG_ 2417880675 S2P_Response_Byte5_35 "根据功能码定义和解析数据3";
CM_ SG_ 2417880675 S2P_Response_Byte6_35 "根据功能码定义和解析数据4";
CM_ SG_ 2417880675 S2P_Response_Byte7_35 "根据功能码定义和解析数据5";
CM_ SG_ 2417880675 S2P_Response_Byte8_35 "根据功能码定义和解析数据6";
CM_ SG_ 2417880676 S2P_Response_Byte1_36 "新增功能使用：";
CM_ SG_ 2417880676 S2P_Response_Byte2_36 "新增功能使用： 功能编码，根据功能定义具含义";
CM_ SG_ 2417880676 S2P_Response_Byte3_36 "根据功能码定义和解析数据1";
CM_ SG_ 2417880676 S2P_Response_Byte4_36 "根据功能码定义和解析数据2";
CM_ SG_ 2417880676 S2P_Response_Byte5_36 "根据功能码定义和解析数据3";
CM_ SG_ 2417880676 S2P_Response_Byte6_36 "根据功能码定义和解析数据4";
CM_ SG_ 2417880676 S2P_Response_Byte7_36 "根据功能码定义和解析数据5";
CM_ SG_ 2417880676 S2P_Response_Byte8_36 "根据功能码定义和解析数据6";
CM_ SG_ 2417880677 S2P_Response_Byte1_37 "新增功能使用：";
CM_ SG_ 2417880677 S2P_Response_Byte2_37 "新增功能使用： 功能编码，根据功能定义具含义";
CM_ SG_ 2417880677 S2P_Response_Byte3_37 "根据功能码定义和解析数据1";
CM_ SG_ 2417880677 S2P_Response_Byte4_37 "根据功能码定义和解析数据2";
CM_ SG_ 2417880677 S2P_Response_Byte5_37 "根据功能码定义和解析数据3";
CM_ SG_ 2417880677 S2P_Response_Byte6_37 "根据功能码定义和解析数据4";
CM_ SG_ 2417880677 S2P_Response_Byte7_37 "根据功能码定义和解析数据5";
CM_ SG_ 2417880677 S2P_Response_Byte8_37 "根据功能码定义和解析数据6";
CM_ SG_ 2417880678 S2P_Response_Byte1_38 "新增功能使用：";
CM_ SG_ 2417880678 S2P_Response_Byte2_38 "新增功能使用： 功能编码，根据功能定义具含义";
CM_ SG_ 2417880678 S2P_Response_Byte3_38 "根据功能码定义和解析数据1";
CM_ SG_ 2417880678 S2P_Response_Byte4_38 "根据功能码定义和解析数据2";
CM_ SG_ 2417880678 S2P_Response_Byte5_38 "根据功能码定义和解析数据3";
CM_ SG_ 2417880678 S2P_Response_Byte6_38 "根据功能码定义和解析数据4";
CM_ SG_ 2417880678 S2P_Response_Byte7_38 "根据功能码定义和解析数据5";
CM_ SG_ 2417880678 S2P_Response_Byte8_38 "根据功能码定义和解析数据6";
CM_ SG_ 2417880679 S2P_Response_Byte1_39 "新增功能使用：";
CM_ SG_ 2417880679 S2P_Response_Byte2_39 "新增功能使用： 功能编码，根据功能定义具含义";
CM_ SG_ 2417880679 S2P_Response_Byte3_39 "根据功能码定义和解析数据1";
CM_ SG_ 2417880679 S2P_Response_Byte4_39 "根据功能码定义和解析数据2";
CM_ SG_ 2417880679 S2P_Response_Byte5_39 "根据功能码定义和解析数据3";
CM_ SG_ 2417880679 S2P_Response_Byte6_39 "根据功能码定义和解析数据4";
CM_ SG_ 2417880679 S2P_Response_Byte7_39 "根据功能码定义和解析数据5";
CM_ SG_ 2417880679 S2P_Response_Byte8_39 "根据功能码定义和解析数据6";
CM_ SG_ 2417880680 S2P_Response_Byte1_40 "新增功能使用：";
CM_ SG_ 2417880680 S2P_Response_Byte2_40 "新增功能使用： 功能编码，根据功能定义具含义";
CM_ SG_ 2417880680 S2P_Response_Byte3_40 "根据功能码定义和解析数据1";
CM_ SG_ 2417880680 S2P_Response_Byte4_40 "根据功能码定义和解析数据2";
CM_ SG_ 2417880680 S2P_Response_Byte5_40 "根据功能码定义和解析数据3";
CM_ SG_ 2417880680 S2P_Response_Byte6_40 "根据功能码定义和解析数据4";
CM_ SG_ 2417880680 S2P_Response_Byte7_40 "根据功能码定义和解析数据5";
CM_ SG_ 2417880680 S2P_Response_Byte8_40 "根据功能码定义和解析数据6";
CM_ SG_ 2417880681 S2P_Response_Byte1_41 "新增功能使用：";
CM_ SG_ 2417880681 S2P_Response_Byte2_41 "新增功能使用： 功能编码，根据功能定义具含义";
CM_ SG_ 2417880681 S2P_Response_Byte3_41 "根据功能码定义和解析数据1";
CM_ SG_ 2417880681 S2P_Response_Byte4_41 "根据功能码定义和解析数据2";
CM_ SG_ 2417880681 S2P_Response_Byte5_41 "根据功能码定义和解析数据3";
CM_ SG_ 2417880681 S2P_Response_Byte6_41 "根据功能码定义和解析数据4";
CM_ SG_ 2417880681 S2P_Response_Byte7_41 "根据功能码定义和解析数据5";
CM_ SG_ 2417880681 S2P_Response_Byte8_41 "根据功能码定义和解析数据6";
CM_ SG_ 2417880682 S2P_Response_Byte1_42 "新增功能使用：";
CM_ SG_ 2417880682 S2P_Response_Byte2_42 "新增功能使用： 功能编码，根据功能定义具含义";
CM_ SG_ 2417880682 S2P_Response_Byte3_42 "根据功能码定义和解析数据1";
CM_ SG_ 2417880682 S2P_Response_Byte4_42 "根据功能码定义和解析数据2";
CM_ SG_ 2417880682 S2P_Response_Byte5_42 "根据功能码定义和解析数据3";
CM_ SG_ 2417880682 S2P_Response_Byte6_42 "根据功能码定义和解析数据4";
CM_ SG_ 2417880682 S2P_Response_Byte7_42 "根据功能码定义和解析数据5";
CM_ SG_ 2417880682 S2P_Response_Byte8_42 "根据功能码定义和解析数据6";
CM_ SG_ 2417880683 S2P_Response_Byte1_43 "新增功能使用：";
CM_ SG_ 2417880683 S2P_Response_Byte2_43 "新增功能使用： 功能编码，根据功能定义具含义";
CM_ SG_ 2417880683 S2P_Response_Byte3_43 "根据功能码定义和解析数据1";
CM_ SG_ 2417880683 S2P_Response_Byte4_43 "根据功能码定义和解析数据2";
CM_ SG_ 2417880683 S2P_Response_Byte5_43 "根据功能码定义和解析数据3";
CM_ SG_ 2417880683 S2P_Response_Byte6_43 "根据功能码定义和解析数据4";
CM_ SG_ 2417880683 S2P_Response_Byte7_43 "根据功能码定义和解析数据5";
CM_ SG_ 2417880683 S2P_Response_Byte8_43 "根据功能码定义和解析数据6";
CM_ SG_ 2417880684 S2P_Response_Byte1_44 "新增功能使用：";
CM_ SG_ 2417880684 S2P_Response_Byte2_44 "新增功能使用： 功能编码，根据功能定义具含义";
CM_ SG_ 2417880684 S2P_Response_Byte3_44 "根据功能码定义和解析数据1";
CM_ SG_ 2417880684 S2P_Response_Byte4_44 "根据功能码定义和解析数据2";
CM_ SG_ 2417880684 S2P_Response_Byte5_44 "根据功能码定义和解析数据3";
CM_ SG_ 2417880684 S2P_Response_Byte6_44 "根据功能码定义和解析数据4";
CM_ SG_ 2417880684 S2P_Response_Byte7_44 "根据功能码定义和解析数据5";
CM_ SG_ 2417880684 S2P_Response_Byte8_44 "根据功能码定义和解析数据6";
CM_ SG_ 2417880685 S2P_Response_Byte1_45 "新增功能使用：";
CM_ SG_ 2417880685 S2P_Response_Byte2_45 "新增功能使用： 功能编码，根据功能定义具含义";
CM_ SG_ 2417880685 S2P_Response_Byte3_45 "根据功能码定义和解析数据1";
CM_ SG_ 2417880685 S2P_Response_Byte4_45 "根据功能码定义和解析数据2";
CM_ SG_ 2417880685 S2P_Response_Byte5_45 "根据功能码定义和解析数据3";
CM_ SG_ 2417880685 S2P_Response_Byte6_45 "根据功能码定义和解析数据4";
CM_ SG_ 2417880685 S2P_Response_Byte7_45 "根据功能码定义和解析数据5";
CM_ SG_ 2417880685 S2P_Response_Byte8_45 "根据功能码定义和解析数据6";
CM_ SG_ 2417880686 S2P_Response_Byte1_46 "新增功能使用：";
CM_ SG_ 2417880686 S2P_Response_Byte2_46 "新增功能使用： 功能编码，根据功能定义具含义";
CM_ SG_ 2417880686 S2P_Response_Byte3_46 "根据功能码定义和解析数据1";
CM_ SG_ 2417880686 S2P_Response_Byte4_46 "根据功能码定义和解析数据2";
CM_ SG_ 2417880686 S2P_Response_Byte5_46 "根据功能码定义和解析数据3";
CM_ SG_ 2417880686 S2P_Response_Byte6_46 "根据功能码定义和解析数据4";
CM_ SG_ 2417880686 S2P_Response_Byte7_46 "根据功能码定义和解析数据5";
CM_ SG_ 2417880686 S2P_Response_Byte8_46 "根据功能码定义和解析数据6";
CM_ SG_ 2417880687 S2P_Response_Byte1_47 "新增功能使用：";
CM_ SG_ 2417880687 S2P_Response_Byte2_47 "新增功能使用： 功能编码，根据功能定义具含义";
CM_ SG_ 2417880687 S2P_Response_Byte3_47 "根据功能码定义和解析数据1";
CM_ SG_ 2417880687 S2P_Response_Byte4_47 "根据功能码定义和解析数据2";
CM_ SG_ 2417880687 S2P_Response_Byte5_47 "根据功能码定义和解析数据3";
CM_ SG_ 2417880687 S2P_Response_Byte6_47 "根据功能码定义和解析数据4";
CM_ SG_ 2417880687 S2P_Response_Byte7_47 "根据功能码定义和解析数据5";
CM_ SG_ 2417880687 S2P_Response_Byte8_47 "根据功能码定义和解析数据6";
CM_ SG_ 2417880688 S2P_Response_Byte1_48 "新增功能使用：";
CM_ SG_ 2417880688 S2P_Response_Byte2_48 "新增功能使用： 功能编码，根据功能定义具含义";
CM_ SG_ 2417880688 S2P_Response_Byte3_48 "根据功能码定义和解析数据1";
CM_ SG_ 2417880688 S2P_Response_Byte4_48 "根据功能码定义和解析数据2";
CM_ SG_ 2417880688 S2P_Response_Byte5_48 "根据功能码定义和解析数据3";
CM_ SG_ 2417880688 S2P_Response_Byte6_48 "根据功能码定义和解析数据4";
CM_ SG_ 2417880688 S2P_Response_Byte7_48 "根据功能码定义和解析数据5";
CM_ SG_ 2417880688 S2P_Response_Byte8_48 "根据功能码定义和解析数据6";
CM_ SG_ 2417880689 S2P_Response_Byte1_49 "新增功能使用：";
CM_ SG_ 2417880689 S2P_Response_Byte2_49 "新增功能使用： 功能编码，根据功能定义具含义";
CM_ SG_ 2417880689 S2P_Response_Byte3_49 "根据功能码定义和解析数据1";
CM_ SG_ 2417880689 S2P_Response_Byte4_49 "根据功能码定义和解析数据2";
CM_ SG_ 2417880689 S2P_Response_Byte5_49 "根据功能码定义和解析数据3";
CM_ SG_ 2417880689 S2P_Response_Byte6_49 "根据功能码定义和解析数据4";
CM_ SG_ 2417880689 S2P_Response_Byte7_49 "根据功能码定义和解析数据5";
CM_ SG_ 2417880689 S2P_Response_Byte8_49 "根据功能码定义和解析数据6";
CM_ SG_ 2417880690 S2P_Response_Byte1_50 "新增功能使用：";
CM_ SG_ 2417880690 S2P_Response_Byte2_50 "新增功能使用： 功能编码，根据功能定义具含义";
CM_ SG_ 2417880690 S2P_Response_Byte3_50 "根据功能码定义和解析数据1";
CM_ SG_ 2417880690 S2P_Response_Byte4_50 "根据功能码定义和解析数据2";
CM_ SG_ 2417880690 S2P_Response_Byte5_50 "根据功能码定义和解析数据3";
CM_ SG_ 2417880690 S2P_Response_Byte6_50 "根据功能码定义和解析数据4";
CM_ SG_ 2417880690 S2P_Response_Byte7_50 "根据功能码定义和解析数据5";
CM_ SG_ 2417880690 S2P_Response_Byte8_50 "根据功能码定义和解析数据6";
CM_ SG_ 2417880691 S2P_Response_Byte1_51 "新增功能使用：";
CM_ SG_ 2417880691 S2P_Response_Byte2_51 "新增功能使用： 功能编码，根据功能定义具含义";
CM_ SG_ 2417880691 S2P_Response_Byte3_51 "根据功能码定义和解析数据1";
CM_ SG_ 2417880691 S2P_Response_Byte4_51 "根据功能码定义和解析数据2";
CM_ SG_ 2417880691 S2P_Response_Byte5_51 "根据功能码定义和解析数据3";
CM_ SG_ 2417880691 S2P_Response_Byte6_51 "根据功能码定义和解析数据4";
CM_ SG_ 2417880691 S2P_Response_Byte7_51 "根据功能码定义和解析数据5";
CM_ SG_ 2417880691 S2P_Response_Byte8_51 "根据功能码定义和解析数据6";
CM_ SG_ 2417880692 S2P_Response_Byte1_52 "新增功能使用：";
CM_ SG_ 2417880692 S2P_Response_Byte2_52 "新增功能使用： 功能编码，根据功能定义具含义";
CM_ SG_ 2417880692 S2P_Response_Byte3_52 "根据功能码定义和解析数据1";
CM_ SG_ 2417880692 S2P_Response_Byte4_52 "根据功能码定义和解析数据2";
CM_ SG_ 2417880692 S2P_Response_Byte5_52 "根据功能码定义和解析数据3";
CM_ SG_ 2417880692 S2P_Response_Byte6_52 "根据功能码定义和解析数据4";
CM_ SG_ 2417880692 S2P_Response_Byte7_52 "根据功能码定义和解析数据5";
CM_ SG_ 2417880692 S2P_Response_Byte8_52 "根据功能码定义和解析数据6";
CM_ SG_ 2417880693 S2P_Response_Byte1_53 "新增功能使用：";
CM_ SG_ 2417880693 S2P_Response_Byte2_53 "新增功能使用： 功能编码，根据功能定义具含义";
CM_ SG_ 2417880693 S2P_Response_Byte3_53 "根据功能码定义和解析数据1";
CM_ SG_ 2417880693 S2P_Response_Byte4_53 "根据功能码定义和解析数据2";
CM_ SG_ 2417880693 S2P_Response_Byte5_53 "根据功能码定义和解析数据3";
CM_ SG_ 2417880693 S2P_Response_Byte6_53 "根据功能码定义和解析数据4";
CM_ SG_ 2417880693 S2P_Response_Byte7_53 "根据功能码定义和解析数据5";
CM_ SG_ 2417880693 S2P_Response_Byte8_53 "根据功能码定义和解析数据6";
CM_ SG_ 2417880694 S2P_Response_Byte1_54 "新增功能使用：";
CM_ SG_ 2417880694 S2P_Response_Byte2_54 "新增功能使用： 功能编码，根据功能定义具含义";
CM_ SG_ 2417880694 S2P_Response_Byte3_54 "根据功能码定义和解析数据1";
CM_ SG_ 2417880694 S2P_Response_Byte4_54 "根据功能码定义和解析数据2";
CM_ SG_ 2417880694 S2P_Response_Byte5_54 "根据功能码定义和解析数据3";
CM_ SG_ 2417880694 S2P_Response_Byte6_54 "根据功能码定义和解析数据4";
CM_ SG_ 2417880694 S2P_Response_Byte7_54 "根据功能码定义和解析数据5";
CM_ SG_ 2417880694 S2P_Response_Byte8_54 "根据功能码定义和解析数据6";
CM_ SG_ 2417880695 S2P_Response_Byte1_55 "新增功能使用：";
CM_ SG_ 2417880695 S2P_Response_Byte2_55 "新增功能使用： 功能编码，根据功能定义具含义";
CM_ SG_ 2417880695 S2P_Response_Byte3_55 "根据功能码定义和解析数据1";
CM_ SG_ 2417880695 S2P_Response_Byte4_55 "根据功能码定义和解析数据2";
CM_ SG_ 2417880695 S2P_Response_Byte5_55 "根据功能码定义和解析数据3";
CM_ SG_ 2417880695 S2P_Response_Byte6_55 "根据功能码定义和解析数据4";
CM_ SG_ 2417880695 S2P_Response_Byte7_55 "根据功能码定义和解析数据5";
CM_ SG_ 2417880695 S2P_Response_Byte8_55 "根据功能码定义和解析数据6";
CM_ SG_ 2417880696 S2P_Response_Byte1_56 "新增功能使用：";
CM_ SG_ 2417880696 S2P_Response_Byte2_56 "新增功能使用： 功能编码，根据功能定义具含义";
CM_ SG_ 2417880696 S2P_Response_Byte3_56 "根据功能码定义和解析数据1";
CM_ SG_ 2417880696 S2P_Response_Byte4_56 "根据功能码定义和解析数据2";
CM_ SG_ 2417880696 S2P_Response_Byte5_56 "根据功能码定义和解析数据3";
CM_ SG_ 2417880696 S2P_Response_Byte6_56 "根据功能码定义和解析数据4";
CM_ SG_ 2417880696 S2P_Response_Byte7_56 "根据功能码定义和解析数据5";
CM_ SG_ 2417880696 S2P_Response_Byte8_56 "根据功能码定义和解析数据6";
CM_ SG_ 2417880697 S2P_Response_Byte1_57 "新增功能使用：";
CM_ SG_ 2417880697 S2P_Response_Byte2_57 "新增功能使用： 功能编码，根据功能定义具含义";
CM_ SG_ 2417880697 S2P_Response_Byte3_57 "根据功能码定义和解析数据1";
CM_ SG_ 2417880697 S2P_Response_Byte4_57 "根据功能码定义和解析数据2";
CM_ SG_ 2417880697 S2P_Response_Byte5_57 "根据功能码定义和解析数据3";
CM_ SG_ 2417880697 S2P_Response_Byte6_57 "根据功能码定义和解析数据4";
CM_ SG_ 2417880697 S2P_Response_Byte7_57 "根据功能码定义和解析数据5";
CM_ SG_ 2417880697 S2P_Response_Byte8_57 "根据功能码定义和解析数据6";
CM_ SG_ 2417880698 S2P_Response_Byte1_58 "新增功能使用：";
CM_ SG_ 2417880698 S2P_Response_Byte2_58 "新增功能使用： 功能编码，根据功能定义具含义";
CM_ SG_ 2417880698 S2P_Response_Byte3_58 "根据功能码定义和解析数据1";
CM_ SG_ 2417880698 S2P_Response_Byte4_58 "根据功能码定义和解析数据2";
CM_ SG_ 2417880698 S2P_Response_Byte5_58 "根据功能码定义和解析数据3";
CM_ SG_ 2417880698 S2P_Response_Byte6_58 "根据功能码定义和解析数据4";
CM_ SG_ 2417880698 S2P_Response_Byte7_58 "根据功能码定义和解析数据5";
CM_ SG_ 2417880698 S2P_Response_Byte8_58 "根据功能码定义和解析数据6";
CM_ SG_ 2417880699 S2P_Response_Byte1_59 "新增功能使用：";
CM_ SG_ 2417880699 S2P_Response_Byte2_59 "新增功能使用： 功能编码，根据功能定义具含义";
CM_ SG_ 2417880699 S2P_Response_Byte3_59 "根据功能码定义和解析数据1";
CM_ SG_ 2417880699 S2P_Response_Byte4_59 "根据功能码定义和解析数据2";
CM_ SG_ 2417880699 S2P_Response_Byte5_59 "根据功能码定义和解析数据3";
CM_ SG_ 2417880699 S2P_Response_Byte6_59 "根据功能码定义和解析数据4";
CM_ SG_ 2417880699 S2P_Response_Byte7_59 "根据功能码定义和解析数据5";
CM_ SG_ 2417880699 S2P_Response_Byte8_59 "根据功能码定义和解析数据6";
CM_ SG_ 2417880700 S2P_Response_Byte1_60 "新增功能使用：";
CM_ SG_ 2417880700 S2P_Response_Byte2_60 "新增功能使用： 功能编码，根据功能定义具含义";
CM_ SG_ 2417880700 S2P_Response_Byte3_60 "根据功能码定义和解析数据1";
CM_ SG_ 2417880700 S2P_Response_Byte4_60 "根据功能码定义和解析数据2";
CM_ SG_ 2417880700 S2P_Response_Byte5_60 "根据功能码定义和解析数据3";
CM_ SG_ 2417880700 S2P_Response_Byte6_60 "根据功能码定义和解析数据4";
CM_ SG_ 2417880700 S2P_Response_Byte7_60 "根据功能码定义和解析数据5";
CM_ SG_ 2417880700 S2P_Response_Byte8_60 "根据功能码定义和解析数据6";
CM_ SG_ 2417880701 S2P_Response_Byte1_61 "新增功能使用：";
CM_ SG_ 2417880701 S2P_Response_Byte2_61 "新增功能使用： 功能编码，根据功能定义具含义";
CM_ SG_ 2417880701 S2P_Response_Byte3_61 "根据功能码定义和解析数据1";
CM_ SG_ 2417880701 S2P_Response_Byte4_61 "根据功能码定义和解析数据2";
CM_ SG_ 2417880701 S2P_Response_Byte5_61 "根据功能码定义和解析数据3";
CM_ SG_ 2417880701 S2P_Response_Byte6_61 "根据功能码定义和解析数据4";
CM_ SG_ 2417880701 S2P_Response_Byte7_61 "根据功能码定义和解析数据5";
CM_ SG_ 2417880701 S2P_Response_Byte8_61 "根据功能码定义和解析数据6";
CM_ SG_ 2417880702 S2P_Response_Byte1_62 "新增功能使用：";
CM_ SG_ 2417880702 S2P_Response_Byte2_62 "新增功能使用： 功能编码，根据功能定义具含义";
CM_ SG_ 2417880702 S2P_Response_Byte3_62 "根据功能码定义和解析数据1";
CM_ SG_ 2417880702 S2P_Response_Byte4_62 "根据功能码定义和解析数据2";
CM_ SG_ 2417880702 S2P_Response_Byte5_62 "根据功能码定义和解析数据3";
CM_ SG_ 2417880702 S2P_Response_Byte6_62 "根据功能码定义和解析数据4";
CM_ SG_ 2417880702 S2P_Response_Byte7_62 "根据功能码定义和解析数据5";
CM_ SG_ 2417880702 S2P_Response_Byte8_62 "根据功能码定义和解析数据6";
CM_ SG_ 2417880703 S2P_Response_Byte1_63 "新增功能使用：";
CM_ SG_ 2417880703 S2P_Response_Byte2_63 "新增功能使用： 功能编码，根据功能定义具含义";
CM_ SG_ 2417880703 S2P_Response_Byte3_63 "根据功能码定义和解析数据1";
CM_ SG_ 2417880703 S2P_Response_Byte4_63 "根据功能码定义和解析数据2";
CM_ SG_ 2417880703 S2P_Response_Byte5_63 "根据功能码定义和解析数据3";
CM_ SG_ 2417880703 S2P_Response_Byte6_63 "根据功能码定义和解析数据4";
CM_ SG_ 2417880703 S2P_Response_Byte7_63 "根据功能码定义和解析数据5";
CM_ SG_ 2417880703 S2P_Response_Byte8_63 "根据功能码定义和解析数据6";
CM_ SG_ 2418601537 S2P_Cfg12_SW_Ver_Byte1_01 "CSC软件版本号最低字节Byte1对应的ASCII码(国产MCU)";
CM_ SG_ 2418601537 S2P_Cfg12_SW_Ver_Byte2_01 "CSC软件版本号Byte2对应的ASCII码(国产MCU)";
CM_ SG_ 2418601537 S2P_Cfg12_SW_Ver_Byte3_01 "CSC软件版本号Byte3对应的ASCII码(国产MCU)";
CM_ SG_ 2418601537 S2P_Cfg12_SW_Ver_Byte4_01 "CSC软件版本号Byte4对应的ASCII码(国产MCU)";
CM_ SG_ 2418601537 S2P_Cfg12_SW_Ver_Byte5_01 "CSC软件版本号Byte5对应的ASCII码(国产MCU)";
CM_ SG_ 2418601537 S2P_Cfg12_SW_Ver_Byte6_01 "CSC软件版本号Byte6对应的ASCII码(国产MCU)";
CM_ SG_ 2418601537 S2P_Cfg12_SW_Ver_Byte7_01 "CSC软件版本号Byte7对应的ASCII码(国产MCU)";
CM_ SG_ 2418601537 S2P_Cfg12_SW_Ver_Byte8_01 "CSC软件版本号Byte8对应的ASCII码(国产MCU)";
CM_ SG_ 2418601538 S2P_Cfg12_SW_Ver_Byte1_02 "CSC软件版本号最低字节Byte1对应的ASCII码(国产MCU)";
CM_ SG_ 2418601538 S2P_Cfg12_SW_Ver_Byte2_02 "CSC软件版本号Byte2对应的ASCII码(国产MCU)";
CM_ SG_ 2418601538 S2P_Cfg12_SW_Ver_Byte3_02 "CSC软件版本号Byte3对应的ASCII码(国产MCU)";
CM_ SG_ 2418601538 S2P_Cfg12_SW_Ver_Byte4_02 "CSC软件版本号Byte4对应的ASCII码(国产MCU)";
CM_ SG_ 2418601538 S2P_Cfg12_SW_Ver_Byte5_02 "CSC软件版本号Byte5对应的ASCII码(国产MCU)";
CM_ SG_ 2418601538 S2P_Cfg12_SW_Ver_Byte6_02 "CSC软件版本号Byte6对应的ASCII码(国产MCU)";
CM_ SG_ 2418601538 S2P_Cfg12_SW_Ver_Byte7_02 "CSC软件版本号Byte7对应的ASCII码(国产MCU)";
CM_ SG_ 2418601538 S2P_Cfg12_SW_Ver_Byte8_02 "CSC软件版本号Byte8对应的ASCII码(国产MCU)";
CM_ SG_ 2418601539 S2P_Cfg12_SW_Ver_Byte1_03 "CSC软件版本号最低字节Byte1对应的ASCII码(国产MCU)";
CM_ SG_ 2418601539 S2P_Cfg12_SW_Ver_Byte2_03 "CSC软件版本号Byte2对应的ASCII码(国产MCU)";
CM_ SG_ 2418601539 S2P_Cfg12_SW_Ver_Byte3_03 "CSC软件版本号Byte3对应的ASCII码(国产MCU)";
CM_ SG_ 2418601539 S2P_Cfg12_SW_Ver_Byte4_03 "CSC软件版本号Byte4对应的ASCII码(国产MCU)";
CM_ SG_ 2418601539 S2P_Cfg12_SW_Ver_Byte5_03 "CSC软件版本号Byte5对应的ASCII码(国产MCU)";
CM_ SG_ 2418601539 S2P_Cfg12_SW_Ver_Byte6_03 "CSC软件版本号Byte6对应的ASCII码(国产MCU)";
CM_ SG_ 2418601539 S2P_Cfg12_SW_Ver_Byte7_03 "CSC软件版本号Byte7对应的ASCII码(国产MCU)";
CM_ SG_ 2418601539 S2P_Cfg12_SW_Ver_Byte8_03 "CSC软件版本号Byte8对应的ASCII码(国产MCU)";
CM_ SG_ 2418601540 S2P_Cfg12_SW_Ver_Byte1_04 "CSC软件版本号最低字节Byte1对应的ASCII码(国产MCU)";
CM_ SG_ 2418601540 S2P_Cfg12_SW_Ver_Byte2_04 "CSC软件版本号Byte2对应的ASCII码(国产MCU)";
CM_ SG_ 2418601540 S2P_Cfg12_SW_Ver_Byte3_04 "CSC软件版本号Byte3对应的ASCII码(国产MCU)";
CM_ SG_ 2418601540 S2P_Cfg12_SW_Ver_Byte4_04 "CSC软件版本号Byte4对应的ASCII码(国产MCU)";
CM_ SG_ 2418601540 S2P_Cfg12_SW_Ver_Byte5_04 "CSC软件版本号Byte5对应的ASCII码(国产MCU)";
CM_ SG_ 2418601540 S2P_Cfg12_SW_Ver_Byte6_04 "CSC软件版本号Byte6对应的ASCII码(国产MCU)";
CM_ SG_ 2418601540 S2P_Cfg12_SW_Ver_Byte7_04 "CSC软件版本号Byte7对应的ASCII码(国产MCU)";
CM_ SG_ 2418601540 S2P_Cfg12_SW_Ver_Byte8_04 "CSC软件版本号Byte8对应的ASCII码(国产MCU)";
CM_ SG_ 2418601541 S2P_Cfg12_SW_Ver_Byte1_05 "CSC软件版本号最低字节Byte1对应的ASCII码(国产MCU)";
CM_ SG_ 2418601541 S2P_Cfg12_SW_Ver_Byte2_05 "CSC软件版本号Byte2对应的ASCII码(国产MCU)";
CM_ SG_ 2418601541 S2P_Cfg12_SW_Ver_Byte3_05 "CSC软件版本号Byte3对应的ASCII码(国产MCU)";
CM_ SG_ 2418601541 S2P_Cfg12_SW_Ver_Byte4_05 "CSC软件版本号Byte4对应的ASCII码(国产MCU)";
CM_ SG_ 2418601541 S2P_Cfg12_SW_Ver_Byte5_05 "CSC软件版本号Byte5对应的ASCII码(国产MCU)";
CM_ SG_ 2418601541 S2P_Cfg12_SW_Ver_Byte6_05 "CSC软件版本号Byte6对应的ASCII码(国产MCU)";
CM_ SG_ 2418601541 S2P_Cfg12_SW_Ver_Byte7_05 "CSC软件版本号Byte7对应的ASCII码(国产MCU)";
CM_ SG_ 2418601541 S2P_Cfg12_SW_Ver_Byte8_05 "CSC软件版本号Byte8对应的ASCII码(国产MCU)";
CM_ SG_ 2418601542 S2P_Cfg12_SW_Ver_Byte1_06 "CSC软件版本号最低字节Byte1对应的ASCII码(国产MCU)";
CM_ SG_ 2418601542 S2P_Cfg12_SW_Ver_Byte2_06 "CSC软件版本号Byte2对应的ASCII码(国产MCU)";
CM_ SG_ 2418601542 S2P_Cfg12_SW_Ver_Byte3_06 "CSC软件版本号Byte3对应的ASCII码(国产MCU)";
CM_ SG_ 2418601542 S2P_Cfg12_SW_Ver_Byte4_06 "CSC软件版本号Byte4对应的ASCII码(国产MCU)";
CM_ SG_ 2418601542 S2P_Cfg12_SW_Ver_Byte5_06 "CSC软件版本号Byte5对应的ASCII码(国产MCU)";
CM_ SG_ 2418601542 S2P_Cfg12_SW_Ver_Byte6_06 "CSC软件版本号Byte6对应的ASCII码(国产MCU)";
CM_ SG_ 2418601542 S2P_Cfg12_SW_Ver_Byte7_06 "CSC软件版本号Byte7对应的ASCII码(国产MCU)";
CM_ SG_ 2418601542 S2P_Cfg12_SW_Ver_Byte8_06 "CSC软件版本号Byte8对应的ASCII码(国产MCU)";
CM_ SG_ 2418601543 S2P_Cfg12_SW_Ver_Byte1_07 "CSC软件版本号最低字节Byte1对应的ASCII码(国产MCU)";
CM_ SG_ 2418601543 S2P_Cfg12_SW_Ver_Byte2_07 "CSC软件版本号Byte2对应的ASCII码(国产MCU)";
CM_ SG_ 2418601543 S2P_Cfg12_SW_Ver_Byte3_07 "CSC软件版本号Byte3对应的ASCII码(国产MCU)";
CM_ SG_ 2418601543 S2P_Cfg12_SW_Ver_Byte4_07 "CSC软件版本号Byte4对应的ASCII码(国产MCU)";
CM_ SG_ 2418601543 S2P_Cfg12_SW_Ver_Byte5_07 "CSC软件版本号Byte5对应的ASCII码(国产MCU)";
CM_ SG_ 2418601543 S2P_Cfg12_SW_Ver_Byte6_07 "CSC软件版本号Byte6对应的ASCII码(国产MCU)";
CM_ SG_ 2418601543 S2P_Cfg12_SW_Ver_Byte7_07 "CSC软件版本号Byte7对应的ASCII码(国产MCU)";
CM_ SG_ 2418601543 S2P_Cfg12_SW_Ver_Byte8_07 "CSC软件版本号Byte8对应的ASCII码(国产MCU)";
CM_ SG_ 2418601544 S2P_Cfg12_SW_Ver_Byte1_08 "CSC软件版本号最低字节Byte1对应的ASCII码(国产MCU)";
CM_ SG_ 2418601544 S2P_Cfg12_SW_Ver_Byte2_08 "CSC软件版本号Byte2对应的ASCII码(国产MCU)";
CM_ SG_ 2418601544 S2P_Cfg12_SW_Ver_Byte3_08 "CSC软件版本号Byte3对应的ASCII码(国产MCU)";
CM_ SG_ 2418601544 S2P_Cfg12_SW_Ver_Byte4_08 "CSC软件版本号Byte4对应的ASCII码(国产MCU)";
CM_ SG_ 2418601544 S2P_Cfg12_SW_Ver_Byte5_08 "CSC软件版本号Byte5对应的ASCII码(国产MCU)";
CM_ SG_ 2418601544 S2P_Cfg12_SW_Ver_Byte6_08 "CSC软件版本号Byte6对应的ASCII码(国产MCU)";
CM_ SG_ 2418601544 S2P_Cfg12_SW_Ver_Byte7_08 "CSC软件版本号Byte7对应的ASCII码(国产MCU)";
CM_ SG_ 2418601544 S2P_Cfg12_SW_Ver_Byte8_08 "CSC软件版本号Byte8对应的ASCII码(国产MCU)";
CM_ SG_ 2418601545 S2P_Cfg12_SW_Ver_Byte1_09 "CSC软件版本号最低字节Byte1对应的ASCII码(国产MCU)";
CM_ SG_ 2418601545 S2P_Cfg12_SW_Ver_Byte2_09 "CSC软件版本号Byte2对应的ASCII码(国产MCU)";
CM_ SG_ 2418601545 S2P_Cfg12_SW_Ver_Byte3_09 "CSC软件版本号Byte3对应的ASCII码(国产MCU)";
CM_ SG_ 2418601545 S2P_Cfg12_SW_Ver_Byte4_09 "CSC软件版本号Byte4对应的ASCII码(国产MCU)";
CM_ SG_ 2418601545 S2P_Cfg12_SW_Ver_Byte5_09 "CSC软件版本号Byte5对应的ASCII码(国产MCU)";
CM_ SG_ 2418601545 S2P_Cfg12_SW_Ver_Byte6_09 "CSC软件版本号Byte6对应的ASCII码(国产MCU)";
CM_ SG_ 2418601545 S2P_Cfg12_SW_Ver_Byte7_09 "CSC软件版本号Byte7对应的ASCII码(国产MCU)";
CM_ SG_ 2418601545 S2P_Cfg12_SW_Ver_Byte8_09 "CSC软件版本号Byte8对应的ASCII码(国产MCU)";
CM_ SG_ 2418601546 S2P_Cfg12_SW_Ver_Byte1_10 "CSC软件版本号最低字节Byte1对应的ASCII码(国产MCU)";
CM_ SG_ 2418601546 S2P_Cfg12_SW_Ver_Byte2_10 "CSC软件版本号Byte2对应的ASCII码(国产MCU)";
CM_ SG_ 2418601546 S2P_Cfg12_SW_Ver_Byte3_10 "CSC软件版本号Byte3对应的ASCII码(国产MCU)";
CM_ SG_ 2418601546 S2P_Cfg12_SW_Ver_Byte4_10 "CSC软件版本号Byte4对应的ASCII码(国产MCU)";
CM_ SG_ 2418601546 S2P_Cfg12_SW_Ver_Byte5_10 "CSC软件版本号Byte5对应的ASCII码(国产MCU)";
CM_ SG_ 2418601546 S2P_Cfg12_SW_Ver_Byte6_10 "CSC软件版本号Byte6对应的ASCII码(国产MCU)";
CM_ SG_ 2418601546 S2P_Cfg12_SW_Ver_Byte7_10 "CSC软件版本号Byte7对应的ASCII码(国产MCU)";
CM_ SG_ 2418601546 S2P_Cfg12_SW_Ver_Byte8_10 "CSC软件版本号Byte8对应的ASCII码(国产MCU)";
CM_ SG_ 2418601547 S2P_Cfg12_SW_Ver_Byte1_11 "CSC软件版本号最低字节Byte1对应的ASCII码(国产MCU)";
CM_ SG_ 2418601547 S2P_Cfg12_SW_Ver_Byte2_11 "CSC软件版本号Byte2对应的ASCII码(国产MCU)";
CM_ SG_ 2418601547 S2P_Cfg12_SW_Ver_Byte3_11 "CSC软件版本号Byte3对应的ASCII码(国产MCU)";
CM_ SG_ 2418601547 S2P_Cfg12_SW_Ver_Byte4_11 "CSC软件版本号Byte4对应的ASCII码(国产MCU)";
CM_ SG_ 2418601547 S2P_Cfg12_SW_Ver_Byte5_11 "CSC软件版本号Byte5对应的ASCII码(国产MCU)";
CM_ SG_ 2418601547 S2P_Cfg12_SW_Ver_Byte6_11 "CSC软件版本号Byte6对应的ASCII码(国产MCU)";
CM_ SG_ 2418601547 S2P_Cfg12_SW_Ver_Byte7_11 "CSC软件版本号Byte7对应的ASCII码(国产MCU)";
CM_ SG_ 2418601547 S2P_Cfg12_SW_Ver_Byte8_11 "CSC软件版本号Byte8对应的ASCII码(国产MCU)";
CM_ SG_ 2418601548 S2P_Cfg12_SW_Ver_Byte1_12 "CSC软件版本号最低字节Byte1对应的ASCII码(国产MCU)";
CM_ SG_ 2418601548 S2P_Cfg12_SW_Ver_Byte2_12 "CSC软件版本号Byte2对应的ASCII码(国产MCU)";
CM_ SG_ 2418601548 S2P_Cfg12_SW_Ver_Byte3_12 "CSC软件版本号Byte3对应的ASCII码(国产MCU)";
CM_ SG_ 2418601548 S2P_Cfg12_SW_Ver_Byte4_12 "CSC软件版本号Byte4对应的ASCII码(国产MCU)";
CM_ SG_ 2418601548 S2P_Cfg12_SW_Ver_Byte5_12 "CSC软件版本号Byte5对应的ASCII码(国产MCU)";
CM_ SG_ 2418601548 S2P_Cfg12_SW_Ver_Byte6_12 "CSC软件版本号Byte6对应的ASCII码(国产MCU)";
CM_ SG_ 2418601548 S2P_Cfg12_SW_Ver_Byte7_12 "CSC软件版本号Byte7对应的ASCII码(国产MCU)";
CM_ SG_ 2418601548 S2P_Cfg12_SW_Ver_Byte8_12 "CSC软件版本号Byte8对应的ASCII码(国产MCU)";
CM_ SG_ 2418601549 S2P_Cfg12_SW_Ver_Byte1_13 "CSC软件版本号最低字节Byte1对应的ASCII码(国产MCU)";
CM_ SG_ 2418601549 S2P_Cfg12_SW_Ver_Byte2_13 "CSC软件版本号Byte2对应的ASCII码(国产MCU)";
CM_ SG_ 2418601549 S2P_Cfg12_SW_Ver_Byte3_13 "CSC软件版本号Byte3对应的ASCII码(国产MCU)";
CM_ SG_ 2418601549 S2P_Cfg12_SW_Ver_Byte4_13 "CSC软件版本号Byte4对应的ASCII码(国产MCU)";
CM_ SG_ 2418601549 S2P_Cfg12_SW_Ver_Byte5_13 "CSC软件版本号Byte5对应的ASCII码(国产MCU)";
CM_ SG_ 2418601549 S2P_Cfg12_SW_Ver_Byte6_13 "CSC软件版本号Byte6对应的ASCII码(国产MCU)";
CM_ SG_ 2418601549 S2P_Cfg12_SW_Ver_Byte7_13 "CSC软件版本号Byte7对应的ASCII码(国产MCU)";
CM_ SG_ 2418601549 S2P_Cfg12_SW_Ver_Byte8_13 "CSC软件版本号Byte8对应的ASCII码(国产MCU)";
CM_ SG_ 2418601550 S2P_Cfg12_SW_Ver_Byte1_14 "CSC软件版本号最低字节Byte1对应的ASCII码(国产MCU)";
CM_ SG_ 2418601550 S2P_Cfg12_SW_Ver_Byte2_14 "CSC软件版本号Byte2对应的ASCII码(国产MCU)";
CM_ SG_ 2418601550 S2P_Cfg12_SW_Ver_Byte3_14 "CSC软件版本号Byte3对应的ASCII码(国产MCU)";
CM_ SG_ 2418601550 S2P_Cfg12_SW_Ver_Byte4_14 "CSC软件版本号Byte4对应的ASCII码(国产MCU)";
CM_ SG_ 2418601550 S2P_Cfg12_SW_Ver_Byte5_14 "CSC软件版本号Byte5对应的ASCII码(国产MCU)";
CM_ SG_ 2418601550 S2P_Cfg12_SW_Ver_Byte6_14 "CSC软件版本号Byte6对应的ASCII码(国产MCU)";
CM_ SG_ 2418601550 S2P_Cfg12_SW_Ver_Byte7_14 "CSC软件版本号Byte7对应的ASCII码(国产MCU)";
CM_ SG_ 2418601550 S2P_Cfg12_SW_Ver_Byte8_14 "CSC软件版本号Byte8对应的ASCII码(国产MCU)";
CM_ SG_ 2418601551 S2P_Cfg12_SW_Ver_Byte1_15 "CSC软件版本号最低字节Byte1对应的ASCII码(国产MCU)";
CM_ SG_ 2418601551 S2P_Cfg12_SW_Ver_Byte2_15 "CSC软件版本号Byte2对应的ASCII码(国产MCU)";
CM_ SG_ 2418601551 S2P_Cfg12_SW_Ver_Byte3_15 "CSC软件版本号Byte3对应的ASCII码(国产MCU)";
CM_ SG_ 2418601551 S2P_Cfg12_SW_Ver_Byte4_15 "CSC软件版本号Byte4对应的ASCII码(国产MCU)";
CM_ SG_ 2418601551 S2P_Cfg12_SW_Ver_Byte5_15 "CSC软件版本号Byte5对应的ASCII码(国产MCU)";
CM_ SG_ 2418601551 S2P_Cfg12_SW_Ver_Byte6_15 "CSC软件版本号Byte6对应的ASCII码(国产MCU)";
CM_ SG_ 2418601551 S2P_Cfg12_SW_Ver_Byte7_15 "CSC软件版本号Byte7对应的ASCII码(国产MCU)";
CM_ SG_ 2418601551 S2P_Cfg12_SW_Ver_Byte8_15 "CSC软件版本号Byte8对应的ASCII码(国产MCU)";
CM_ SG_ 2418601552 S2P_Cfg12_SW_Ver_Byte1_16 "CSC软件版本号最低字节Byte1对应的ASCII码(国产MCU)";
CM_ SG_ 2418601552 S2P_Cfg12_SW_Ver_Byte2_16 "CSC软件版本号Byte2对应的ASCII码(国产MCU)";
CM_ SG_ 2418601552 S2P_Cfg12_SW_Ver_Byte3_16 "CSC软件版本号Byte3对应的ASCII码(国产MCU)";
CM_ SG_ 2418601552 S2P_Cfg12_SW_Ver_Byte4_16 "CSC软件版本号Byte4对应的ASCII码(国产MCU)";
CM_ SG_ 2418601552 S2P_Cfg12_SW_Ver_Byte5_16 "CSC软件版本号Byte5对应的ASCII码(国产MCU)";
CM_ SG_ 2418601552 S2P_Cfg12_SW_Ver_Byte6_16 "CSC软件版本号Byte6对应的ASCII码(国产MCU)";
CM_ SG_ 2418601552 S2P_Cfg12_SW_Ver_Byte7_16 "CSC软件版本号Byte7对应的ASCII码(国产MCU)";
CM_ SG_ 2418601552 S2P_Cfg12_SW_Ver_Byte8_16 "CSC软件版本号Byte8对应的ASCII码(国产MCU)";
CM_ SG_ 2418601553 S2P_Cfg12_SW_Ver_Byte1_17 "CSC软件版本号最低字节Byte1对应的ASCII码(国产MCU)";
CM_ SG_ 2418601553 S2P_Cfg12_SW_Ver_Byte2_17 "CSC软件版本号Byte2对应的ASCII码(国产MCU)";
CM_ SG_ 2418601553 S2P_Cfg12_SW_Ver_Byte3_17 "CSC软件版本号Byte3对应的ASCII码(国产MCU)";
CM_ SG_ 2418601553 S2P_Cfg12_SW_Ver_Byte4_17 "CSC软件版本号Byte4对应的ASCII码(国产MCU)";
CM_ SG_ 2418601553 S2P_Cfg12_SW_Ver_Byte5_17 "CSC软件版本号Byte5对应的ASCII码(国产MCU)";
CM_ SG_ 2418601553 S2P_Cfg12_SW_Ver_Byte6_17 "CSC软件版本号Byte6对应的ASCII码(国产MCU)";
CM_ SG_ 2418601553 S2P_Cfg12_SW_Ver_Byte7_17 "CSC软件版本号Byte7对应的ASCII码(国产MCU)";
CM_ SG_ 2418601553 S2P_Cfg12_SW_Ver_Byte8_17 "CSC软件版本号Byte8对应的ASCII码(国产MCU)";
CM_ SG_ 2418601554 S2P_Cfg12_SW_Ver_Byte1_18 "CSC软件版本号最低字节Byte1对应的ASCII码(国产MCU)";
CM_ SG_ 2418601554 S2P_Cfg12_SW_Ver_Byte2_18 "CSC软件版本号Byte2对应的ASCII码(国产MCU)";
CM_ SG_ 2418601554 S2P_Cfg12_SW_Ver_Byte3_18 "CSC软件版本号Byte3对应的ASCII码(国产MCU)";
CM_ SG_ 2418601554 S2P_Cfg12_SW_Ver_Byte4_18 "CSC软件版本号Byte4对应的ASCII码(国产MCU)";
CM_ SG_ 2418601554 S2P_Cfg12_SW_Ver_Byte5_18 "CSC软件版本号Byte5对应的ASCII码(国产MCU)";
CM_ SG_ 2418601554 S2P_Cfg12_SW_Ver_Byte6_18 "CSC软件版本号Byte6对应的ASCII码(国产MCU)";
CM_ SG_ 2418601554 S2P_Cfg12_SW_Ver_Byte7_18 "CSC软件版本号Byte7对应的ASCII码(国产MCU)";
CM_ SG_ 2418601554 S2P_Cfg12_SW_Ver_Byte8_18 "CSC软件版本号Byte8对应的ASCII码(国产MCU)";
CM_ SG_ 2418601555 S2P_Cfg12_SW_Ver_Byte1_19 "CSC软件版本号最低字节Byte1对应的ASCII码(国产MCU)";
CM_ SG_ 2418601555 S2P_Cfg12_SW_Ver_Byte2_19 "CSC软件版本号Byte2对应的ASCII码(国产MCU)";
CM_ SG_ 2418601555 S2P_Cfg12_SW_Ver_Byte3_19 "CSC软件版本号Byte3对应的ASCII码(国产MCU)";
CM_ SG_ 2418601555 S2P_Cfg12_SW_Ver_Byte4_19 "CSC软件版本号Byte4对应的ASCII码(国产MCU)";
CM_ SG_ 2418601555 S2P_Cfg12_SW_Ver_Byte5_19 "CSC软件版本号Byte5对应的ASCII码(国产MCU)";
CM_ SG_ 2418601555 S2P_Cfg12_SW_Ver_Byte6_19 "CSC软件版本号Byte6对应的ASCII码(国产MCU)";
CM_ SG_ 2418601555 S2P_Cfg12_SW_Ver_Byte7_19 "CSC软件版本号Byte7对应的ASCII码(国产MCU)";
CM_ SG_ 2418601555 S2P_Cfg12_SW_Ver_Byte8_19 "CSC软件版本号Byte8对应的ASCII码(国产MCU)";
CM_ SG_ 2418601556 S2P_Cfg12_SW_Ver_Byte1_20 "CSC软件版本号最低字节Byte1对应的ASCII码(国产MCU)";
CM_ SG_ 2418601556 S2P_Cfg12_SW_Ver_Byte2_20 "CSC软件版本号Byte2对应的ASCII码(国产MCU)";
CM_ SG_ 2418601556 S2P_Cfg12_SW_Ver_Byte3_20 "CSC软件版本号Byte3对应的ASCII码(国产MCU)";
CM_ SG_ 2418601556 S2P_Cfg12_SW_Ver_Byte4_20 "CSC软件版本号Byte4对应的ASCII码(国产MCU)";
CM_ SG_ 2418601556 S2P_Cfg12_SW_Ver_Byte5_20 "CSC软件版本号Byte5对应的ASCII码(国产MCU)";
CM_ SG_ 2418601556 S2P_Cfg12_SW_Ver_Byte6_20 "CSC软件版本号Byte6对应的ASCII码(国产MCU)";
CM_ SG_ 2418601556 S2P_Cfg12_SW_Ver_Byte7_20 "CSC软件版本号Byte7对应的ASCII码(国产MCU)";
CM_ SG_ 2418601556 S2P_Cfg12_SW_Ver_Byte8_20 "CSC软件版本号Byte8对应的ASCII码(国产MCU)";
CM_ SG_ 2418601557 S2P_Cfg12_SW_Ver_Byte1_21 "CSC软件版本号最低字节Byte1对应的ASCII码(国产MCU)";
CM_ SG_ 2418601557 S2P_Cfg12_SW_Ver_Byte2_21 "CSC软件版本号Byte2对应的ASCII码(国产MCU)";
CM_ SG_ 2418601557 S2P_Cfg12_SW_Ver_Byte3_21 "CSC软件版本号Byte3对应的ASCII码(国产MCU)";
CM_ SG_ 2418601557 S2P_Cfg12_SW_Ver_Byte4_21 "CSC软件版本号Byte4对应的ASCII码(国产MCU)";
CM_ SG_ 2418601557 S2P_Cfg12_SW_Ver_Byte5_21 "CSC软件版本号Byte5对应的ASCII码(国产MCU)";
CM_ SG_ 2418601557 S2P_Cfg12_SW_Ver_Byte6_21 "CSC软件版本号Byte6对应的ASCII码(国产MCU)";
CM_ SG_ 2418601557 S2P_Cfg12_SW_Ver_Byte7_21 "CSC软件版本号Byte7对应的ASCII码(国产MCU)";
CM_ SG_ 2418601557 S2P_Cfg12_SW_Ver_Byte8_21 "CSC软件版本号Byte8对应的ASCII码(国产MCU)";
CM_ SG_ 2418601558 S2P_Cfg12_SW_Ver_Byte1_22 "CSC软件版本号最低字节Byte1对应的ASCII码(国产MCU)";
CM_ SG_ 2418601558 S2P_Cfg12_SW_Ver_Byte2_22 "CSC软件版本号Byte2对应的ASCII码(国产MCU)";
CM_ SG_ 2418601558 S2P_Cfg12_SW_Ver_Byte3_22 "CSC软件版本号Byte3对应的ASCII码(国产MCU)";
CM_ SG_ 2418601558 S2P_Cfg12_SW_Ver_Byte4_22 "CSC软件版本号Byte4对应的ASCII码(国产MCU)";
CM_ SG_ 2418601558 S2P_Cfg12_SW_Ver_Byte5_22 "CSC软件版本号Byte5对应的ASCII码(国产MCU)";
CM_ SG_ 2418601558 S2P_Cfg12_SW_Ver_Byte6_22 "CSC软件版本号Byte6对应的ASCII码(国产MCU)";
CM_ SG_ 2418601558 S2P_Cfg12_SW_Ver_Byte7_22 "CSC软件版本号Byte7对应的ASCII码(国产MCU)";
CM_ SG_ 2418601558 S2P_Cfg12_SW_Ver_Byte8_22 "CSC软件版本号Byte8对应的ASCII码(国产MCU)";
CM_ SG_ 2418601559 S2P_Cfg12_SW_Ver_Byte1_23 "CSC软件版本号最低字节Byte1对应的ASCII码(国产MCU)";
CM_ SG_ 2418601559 S2P_Cfg12_SW_Ver_Byte2_23 "CSC软件版本号Byte2对应的ASCII码(国产MCU)";
CM_ SG_ 2418601559 S2P_Cfg12_SW_Ver_Byte3_23 "CSC软件版本号Byte3对应的ASCII码(国产MCU)";
CM_ SG_ 2418601559 S2P_Cfg12_SW_Ver_Byte4_23 "CSC软件版本号Byte4对应的ASCII码(国产MCU)";
CM_ SG_ 2418601559 S2P_Cfg12_SW_Ver_Byte5_23 "CSC软件版本号Byte5对应的ASCII码(国产MCU)";
CM_ SG_ 2418601559 S2P_Cfg12_SW_Ver_Byte6_23 "CSC软件版本号Byte6对应的ASCII码(国产MCU)";
CM_ SG_ 2418601559 S2P_Cfg12_SW_Ver_Byte7_23 "CSC软件版本号Byte7对应的ASCII码(国产MCU)";
CM_ SG_ 2418601559 S2P_Cfg12_SW_Ver_Byte8_23 "CSC软件版本号Byte8对应的ASCII码(国产MCU)";
CM_ SG_ 2418601560 S2P_Cfg12_SW_Ver_Byte1_24 "CSC软件版本号最低字节Byte1对应的ASCII码(国产MCU)";
CM_ SG_ 2418601560 S2P_Cfg12_SW_Ver_Byte2_24 "CSC软件版本号Byte2对应的ASCII码(国产MCU)";
CM_ SG_ 2418601560 S2P_Cfg12_SW_Ver_Byte3_24 "CSC软件版本号Byte3对应的ASCII码(国产MCU)";
CM_ SG_ 2418601560 S2P_Cfg12_SW_Ver_Byte4_24 "CSC软件版本号Byte4对应的ASCII码(国产MCU)";
CM_ SG_ 2418601560 S2P_Cfg12_SW_Ver_Byte5_24 "CSC软件版本号Byte5对应的ASCII码(国产MCU)";
CM_ SG_ 2418601560 S2P_Cfg12_SW_Ver_Byte6_24 "CSC软件版本号Byte6对应的ASCII码(国产MCU)";
CM_ SG_ 2418601560 S2P_Cfg12_SW_Ver_Byte7_24 "CSC软件版本号Byte7对应的ASCII码(国产MCU)";
CM_ SG_ 2418601560 S2P_Cfg12_SW_Ver_Byte8_24 "CSC软件版本号Byte8对应的ASCII码(国产MCU)";
CM_ SG_ 2418601561 S2P_Cfg12_SW_Ver_Byte1_25 "CSC软件版本号最低字节Byte1对应的ASCII码(国产MCU)";
CM_ SG_ 2418601561 S2P_Cfg12_SW_Ver_Byte2_25 "CSC软件版本号Byte2对应的ASCII码(国产MCU)";
CM_ SG_ 2418601561 S2P_Cfg12_SW_Ver_Byte3_25 "CSC软件版本号Byte3对应的ASCII码(国产MCU)";
CM_ SG_ 2418601561 S2P_Cfg12_SW_Ver_Byte4_25 "CSC软件版本号Byte4对应的ASCII码(国产MCU)";
CM_ SG_ 2418601561 S2P_Cfg12_SW_Ver_Byte5_25 "CSC软件版本号Byte5对应的ASCII码(国产MCU)";
CM_ SG_ 2418601561 S2P_Cfg12_SW_Ver_Byte6_25 "CSC软件版本号Byte6对应的ASCII码(国产MCU)";
CM_ SG_ 2418601561 S2P_Cfg12_SW_Ver_Byte7_25 "CSC软件版本号Byte7对应的ASCII码(国产MCU)";
CM_ SG_ 2418601561 S2P_Cfg12_SW_Ver_Byte8_25 "CSC软件版本号Byte8对应的ASCII码(国产MCU)";
CM_ SG_ 2418601562 S2P_Cfg12_SW_Ver_Byte1_26 "CSC软件版本号最低字节Byte1对应的ASCII码(国产MCU)";
CM_ SG_ 2418601562 S2P_Cfg12_SW_Ver_Byte2_26 "CSC软件版本号Byte2对应的ASCII码(国产MCU)";
CM_ SG_ 2418601562 S2P_Cfg12_SW_Ver_Byte3_26 "CSC软件版本号Byte3对应的ASCII码(国产MCU)";
CM_ SG_ 2418601562 S2P_Cfg12_SW_Ver_Byte4_26 "CSC软件版本号Byte4对应的ASCII码(国产MCU)";
CM_ SG_ 2418601562 S2P_Cfg12_SW_Ver_Byte5_26 "CSC软件版本号Byte5对应的ASCII码(国产MCU)";
CM_ SG_ 2418601562 S2P_Cfg12_SW_Ver_Byte6_26 "CSC软件版本号Byte6对应的ASCII码(国产MCU)";
CM_ SG_ 2418601562 S2P_Cfg12_SW_Ver_Byte7_26 "CSC软件版本号Byte7对应的ASCII码(国产MCU)";
CM_ SG_ 2418601562 S2P_Cfg12_SW_Ver_Byte8_26 "CSC软件版本号Byte8对应的ASCII码(国产MCU)";
CM_ SG_ 2418601563 S2P_Cfg12_SW_Ver_Byte1_27 "CSC软件版本号最低字节Byte1对应的ASCII码(国产MCU)";
CM_ SG_ 2418601563 S2P_Cfg12_SW_Ver_Byte2_27 "CSC软件版本号Byte2对应的ASCII码(国产MCU)";
CM_ SG_ 2418601563 S2P_Cfg12_SW_Ver_Byte3_27 "CSC软件版本号Byte3对应的ASCII码(国产MCU)";
CM_ SG_ 2418601563 S2P_Cfg12_SW_Ver_Byte4_27 "CSC软件版本号Byte4对应的ASCII码(国产MCU)";
CM_ SG_ 2418601563 S2P_Cfg12_SW_Ver_Byte5_27 "CSC软件版本号Byte5对应的ASCII码(国产MCU)";
CM_ SG_ 2418601563 S2P_Cfg12_SW_Ver_Byte6_27 "CSC软件版本号Byte6对应的ASCII码(国产MCU)";
CM_ SG_ 2418601563 S2P_Cfg12_SW_Ver_Byte7_27 "CSC软件版本号Byte7对应的ASCII码(国产MCU)";
CM_ SG_ 2418601563 S2P_Cfg12_SW_Ver_Byte8_27 "CSC软件版本号Byte8对应的ASCII码(国产MCU)";
CM_ SG_ 2418601564 S2P_Cfg12_SW_Ver_Byte1_28 "CSC软件版本号最低字节Byte1对应的ASCII码(国产MCU)";
CM_ SG_ 2418601564 S2P_Cfg12_SW_Ver_Byte2_28 "CSC软件版本号Byte2对应的ASCII码(国产MCU)";
CM_ SG_ 2418601564 S2P_Cfg12_SW_Ver_Byte3_28 "CSC软件版本号Byte3对应的ASCII码(国产MCU)";
CM_ SG_ 2418601564 S2P_Cfg12_SW_Ver_Byte4_28 "CSC软件版本号Byte4对应的ASCII码(国产MCU)";
CM_ SG_ 2418601564 S2P_Cfg12_SW_Ver_Byte5_28 "CSC软件版本号Byte5对应的ASCII码(国产MCU)";
CM_ SG_ 2418601564 S2P_Cfg12_SW_Ver_Byte6_28 "CSC软件版本号Byte6对应的ASCII码(国产MCU)";
CM_ SG_ 2418601564 S2P_Cfg12_SW_Ver_Byte7_28 "CSC软件版本号Byte7对应的ASCII码(国产MCU)";
CM_ SG_ 2418601564 S2P_Cfg12_SW_Ver_Byte8_28 "CSC软件版本号Byte8对应的ASCII码(国产MCU)";
CM_ SG_ 2418601565 S2P_Cfg12_SW_Ver_Byte1_29 "CSC软件版本号最低字节Byte1对应的ASCII码(国产MCU)";
CM_ SG_ 2418601565 S2P_Cfg12_SW_Ver_Byte2_29 "CSC软件版本号Byte2对应的ASCII码(国产MCU)";
CM_ SG_ 2418601565 S2P_Cfg12_SW_Ver_Byte3_29 "CSC软件版本号Byte3对应的ASCII码(国产MCU)";
CM_ SG_ 2418601565 S2P_Cfg12_SW_Ver_Byte4_29 "CSC软件版本号Byte4对应的ASCII码(国产MCU)";
CM_ SG_ 2418601565 S2P_Cfg12_SW_Ver_Byte5_29 "CSC软件版本号Byte5对应的ASCII码(国产MCU)";
CM_ SG_ 2418601565 S2P_Cfg12_SW_Ver_Byte6_29 "CSC软件版本号Byte6对应的ASCII码(国产MCU)";
CM_ SG_ 2418601565 S2P_Cfg12_SW_Ver_Byte7_29 "CSC软件版本号Byte7对应的ASCII码(国产MCU)";
CM_ SG_ 2418601565 S2P_Cfg12_SW_Ver_Byte8_29 "CSC软件版本号Byte8对应的ASCII码(国产MCU)";
CM_ SG_ 2418601566 S2P_Cfg12_SW_Ver_Byte1_30 "CSC软件版本号最低字节Byte1对应的ASCII码(国产MCU)";
CM_ SG_ 2418601566 S2P_Cfg12_SW_Ver_Byte2_30 "CSC软件版本号Byte2对应的ASCII码(国产MCU)";
CM_ SG_ 2418601566 S2P_Cfg12_SW_Ver_Byte3_30 "CSC软件版本号Byte3对应的ASCII码(国产MCU)";
CM_ SG_ 2418601566 S2P_Cfg12_SW_Ver_Byte4_30 "CSC软件版本号Byte4对应的ASCII码(国产MCU)";
CM_ SG_ 2418601566 S2P_Cfg12_SW_Ver_Byte5_30 "CSC软件版本号Byte5对应的ASCII码(国产MCU)";
CM_ SG_ 2418601566 S2P_Cfg12_SW_Ver_Byte6_30 "CSC软件版本号Byte6对应的ASCII码(国产MCU)";
CM_ SG_ 2418601566 S2P_Cfg12_SW_Ver_Byte7_30 "CSC软件版本号Byte7对应的ASCII码(国产MCU)";
CM_ SG_ 2418601566 S2P_Cfg12_SW_Ver_Byte8_30 "CSC软件版本号Byte8对应的ASCII码(国产MCU)";
CM_ SG_ 2418601567 S2P_Cfg12_SW_Ver_Byte1_31 "CSC软件版本号最低字节Byte1对应的ASCII码(国产MCU)";
CM_ SG_ 2418601567 S2P_Cfg12_SW_Ver_Byte2_31 "CSC软件版本号Byte2对应的ASCII码(国产MCU)";
CM_ SG_ 2418601567 S2P_Cfg12_SW_Ver_Byte3_31 "CSC软件版本号Byte3对应的ASCII码(国产MCU)";
CM_ SG_ 2418601567 S2P_Cfg12_SW_Ver_Byte4_31 "CSC软件版本号Byte4对应的ASCII码(国产MCU)";
CM_ SG_ 2418601567 S2P_Cfg12_SW_Ver_Byte5_31 "CSC软件版本号Byte5对应的ASCII码(国产MCU)";
CM_ SG_ 2418601567 S2P_Cfg12_SW_Ver_Byte6_31 "CSC软件版本号Byte6对应的ASCII码(国产MCU)";
CM_ SG_ 2418601567 S2P_Cfg12_SW_Ver_Byte7_31 "CSC软件版本号Byte7对应的ASCII码(国产MCU)";
CM_ SG_ 2418601567 S2P_Cfg12_SW_Ver_Byte8_31 "CSC软件版本号Byte8对应的ASCII码(国产MCU)";
CM_ SG_ 2418601568 S2P_Cfg12_SW_Ver_Byte1_32 "CSC软件版本号最低字节Byte1对应的ASCII码(国产MCU)";
CM_ SG_ 2418601568 S2P_Cfg12_SW_Ver_Byte2_32 "CSC软件版本号Byte2对应的ASCII码(国产MCU)";
CM_ SG_ 2418601568 S2P_Cfg12_SW_Ver_Byte3_32 "CSC软件版本号Byte3对应的ASCII码(国产MCU)";
CM_ SG_ 2418601568 S2P_Cfg12_SW_Ver_Byte4_32 "CSC软件版本号Byte4对应的ASCII码(国产MCU)";
CM_ SG_ 2418601568 S2P_Cfg12_SW_Ver_Byte5_32 "CSC软件版本号Byte5对应的ASCII码(国产MCU)";
CM_ SG_ 2418601568 S2P_Cfg12_SW_Ver_Byte6_32 "CSC软件版本号Byte6对应的ASCII码(国产MCU)";
CM_ SG_ 2418601568 S2P_Cfg12_SW_Ver_Byte7_32 "CSC软件版本号Byte7对应的ASCII码(国产MCU)";
CM_ SG_ 2418601568 S2P_Cfg12_SW_Ver_Byte8_32 "CSC软件版本号Byte8对应的ASCII码(国产MCU)";
CM_ SG_ 2418601569 S2P_Cfg12_SW_Ver_Byte1_33 "CSC软件版本号最低字节Byte1对应的ASCII码(国产MCU)";
CM_ SG_ 2418601569 S2P_Cfg12_SW_Ver_Byte2_33 "CSC软件版本号Byte2对应的ASCII码(国产MCU)";
CM_ SG_ 2418601569 S2P_Cfg12_SW_Ver_Byte3_33 "CSC软件版本号Byte3对应的ASCII码(国产MCU)";
CM_ SG_ 2418601569 S2P_Cfg12_SW_Ver_Byte4_33 "CSC软件版本号Byte4对应的ASCII码(国产MCU)";
CM_ SG_ 2418601569 S2P_Cfg12_SW_Ver_Byte5_33 "CSC软件版本号Byte5对应的ASCII码(国产MCU)";
CM_ SG_ 2418601569 S2P_Cfg12_SW_Ver_Byte6_33 "CSC软件版本号Byte6对应的ASCII码(国产MCU)";
CM_ SG_ 2418601569 S2P_Cfg12_SW_Ver_Byte7_33 "CSC软件版本号Byte7对应的ASCII码(国产MCU)";
CM_ SG_ 2418601569 S2P_Cfg12_SW_Ver_Byte8_33 "CSC软件版本号Byte8对应的ASCII码(国产MCU)";
CM_ SG_ 2418601570 S2P_Cfg12_SW_Ver_Byte1_34 "CSC软件版本号最低字节Byte1对应的ASCII码(国产MCU)";
CM_ SG_ 2418601570 S2P_Cfg12_SW_Ver_Byte2_34 "CSC软件版本号Byte2对应的ASCII码(国产MCU)";
CM_ SG_ 2418601570 S2P_Cfg12_SW_Ver_Byte3_34 "CSC软件版本号Byte3对应的ASCII码(国产MCU)";
CM_ SG_ 2418601570 S2P_Cfg12_SW_Ver_Byte4_34 "CSC软件版本号Byte4对应的ASCII码(国产MCU)";
CM_ SG_ 2418601570 S2P_Cfg12_SW_Ver_Byte5_34 "CSC软件版本号Byte5对应的ASCII码(国产MCU)";
CM_ SG_ 2418601570 S2P_Cfg12_SW_Ver_Byte6_34 "CSC软件版本号Byte6对应的ASCII码(国产MCU)";
CM_ SG_ 2418601570 S2P_Cfg12_SW_Ver_Byte7_34 "CSC软件版本号Byte7对应的ASCII码(国产MCU)";
CM_ SG_ 2418601570 S2P_Cfg12_SW_Ver_Byte8_34 "CSC软件版本号Byte8对应的ASCII码(国产MCU)";
CM_ SG_ 2418601571 S2P_Cfg12_SW_Ver_Byte1_35 "CSC软件版本号最低字节Byte1对应的ASCII码(国产MCU)";
CM_ SG_ 2418601571 S2P_Cfg12_SW_Ver_Byte2_35 "CSC软件版本号Byte2对应的ASCII码(国产MCU)";
CM_ SG_ 2418601571 S2P_Cfg12_SW_Ver_Byte3_35 "CSC软件版本号Byte3对应的ASCII码(国产MCU)";
CM_ SG_ 2418601571 S2P_Cfg12_SW_Ver_Byte4_35 "CSC软件版本号Byte4对应的ASCII码(国产MCU)";
CM_ SG_ 2418601571 S2P_Cfg12_SW_Ver_Byte5_35 "CSC软件版本号Byte5对应的ASCII码(国产MCU)";
CM_ SG_ 2418601571 S2P_Cfg12_SW_Ver_Byte6_35 "CSC软件版本号Byte6对应的ASCII码(国产MCU)";
CM_ SG_ 2418601571 S2P_Cfg12_SW_Ver_Byte7_35 "CSC软件版本号Byte7对应的ASCII码(国产MCU)";
CM_ SG_ 2418601571 S2P_Cfg12_SW_Ver_Byte8_35 "CSC软件版本号Byte8对应的ASCII码(国产MCU)";
CM_ SG_ 2418601572 S2P_Cfg12_SW_Ver_Byte1_36 "CSC软件版本号最低字节Byte1对应的ASCII码(国产MCU)";
CM_ SG_ 2418601572 S2P_Cfg12_SW_Ver_Byte2_36 "CSC软件版本号Byte2对应的ASCII码(国产MCU)";
CM_ SG_ 2418601572 S2P_Cfg12_SW_Ver_Byte3_36 "CSC软件版本号Byte3对应的ASCII码(国产MCU)";
CM_ SG_ 2418601572 S2P_Cfg12_SW_Ver_Byte4_36 "CSC软件版本号Byte4对应的ASCII码(国产MCU)";
CM_ SG_ 2418601572 S2P_Cfg12_SW_Ver_Byte5_36 "CSC软件版本号Byte5对应的ASCII码(国产MCU)";
CM_ SG_ 2418601572 S2P_Cfg12_SW_Ver_Byte6_36 "CSC软件版本号Byte6对应的ASCII码(国产MCU)";
CM_ SG_ 2418601572 S2P_Cfg12_SW_Ver_Byte7_36 "CSC软件版本号Byte7对应的ASCII码(国产MCU)";
CM_ SG_ 2418601572 S2P_Cfg12_SW_Ver_Byte8_36 "CSC软件版本号Byte8对应的ASCII码(国产MCU)";
CM_ SG_ 2418601573 S2P_Cfg12_SW_Ver_Byte1_37 "CSC软件版本号最低字节Byte1对应的ASCII码(国产MCU)";
CM_ SG_ 2418601573 S2P_Cfg12_SW_Ver_Byte2_37 "CSC软件版本号Byte2对应的ASCII码(国产MCU)";
CM_ SG_ 2418601573 S2P_Cfg12_SW_Ver_Byte3_37 "CSC软件版本号Byte3对应的ASCII码(国产MCU)";
CM_ SG_ 2418601573 S2P_Cfg12_SW_Ver_Byte4_37 "CSC软件版本号Byte4对应的ASCII码(国产MCU)";
CM_ SG_ 2418601573 S2P_Cfg12_SW_Ver_Byte5_37 "CSC软件版本号Byte5对应的ASCII码(国产MCU)";
CM_ SG_ 2418601573 S2P_Cfg12_SW_Ver_Byte6_37 "CSC软件版本号Byte6对应的ASCII码(国产MCU)";
CM_ SG_ 2418601573 S2P_Cfg12_SW_Ver_Byte7_37 "CSC软件版本号Byte7对应的ASCII码(国产MCU)";
CM_ SG_ 2418601573 S2P_Cfg12_SW_Ver_Byte8_37 "CSC软件版本号Byte8对应的ASCII码(国产MCU)";
VAL_ 2148892563 U2T_BMS_ControlMode_2 0 "关机模式" 1 "制冷模式" 2 "加热模式" 3 "自循环模式" ;
VAL_ 2148892563 T2U_TMS_RunState_2 0 "关机模式" 1 "制冷模式" 2 "加热模式" 3 "自循环模式" ;
VAL_ 2148892563 T2U_TMS_FaultCode_2 0 "无故障" ;
VAL_ 2148892563 T2U_TMS_FaultLevel_2 0 "无效" 1 "1级故障" 2 "2级故障" 3 "3级故障" ;
VAL_ 2148892563 U2T_BMS_TmptSetPoint_2 255 "Invalid" ;
VAL_ 2148892563 T2U_TMS_OutWaterTemp_2 255 "无效" ;
VAL_ 2148892563 T2U_TMS_BackWaterTemp_2 255 "无效" ;
VAL_ 2148892563 T2U_TMS_EnvTemp_2 255 "无效" ;
VAL_ 2148892563 M2P_TMS_OvrTmpLwFltLvl3_2_03 0 "制冷模式正常" 1 "环境温度超过55℃制冷保护或环境温度低于-40℃制冷保护" ;
VAL_ 2148892564 U2T_BMS_ControlMode_2 0 "关机模式" 1 "制冷模式" 2 "加热模式" 3 "自循环模式" ;
VAL_ 2148892564 T2U_TMS_RunState_2 0 "关机模式" 1 "制冷模式" 2 "加热模式" 3 "自循环模式" ;
VAL_ 2148892564 T2U_TMS_FaultCode_2 0 "无故障" ;
VAL_ 2148892564 T2U_TMS_FaultLevel_2 0 "无效" 1 "1级故障" 2 "2级故障" 3 "3级故障" ;
VAL_ 2148892564 U2T_BMS_TmptSetPoint_2 255 "Invalid" ;
VAL_ 2148892564 T2U_TMS_OutWaterTemp_2 255 "无效" ;
VAL_ 2148892564 T2U_TMS_BackWaterTemp_2 255 "无效" ;
VAL_ 2148892564 T2U_TMS_EnvTemp_2 255 "无效" ;
VAL_ 2148892564 M2P_TMS_OvrTmpLwFltLvl3_2_04 0 "制冷模式正常" 1 "环境温度超过55℃制冷保护或环境温度低于-40℃制冷保护" ;
VAL_ 2148892565 U2T_BMS_ControlMode_2 0 "关机模式" 1 "制冷模式" 2 "加热模式" 3 "自循环模式" ;
VAL_ 2148892565 T2U_TMS_RunState_2 0 "关机模式" 1 "制冷模式" 2 "加热模式" 3 "自循环模式" ;
VAL_ 2148892565 T2U_TMS_FaultCode_2 0 "无故障" ;
VAL_ 2148892565 T2U_TMS_FaultLevel_2 0 "无效" 1 "1级故障" 2 "2级故障" 3 "3级故障" ;
VAL_ 2148892565 U2T_BMS_TmptSetPoint_2 255 "Invalid" ;
VAL_ 2148892565 T2U_TMS_OutWaterTemp_2 255 "无效" ;
VAL_ 2148892565 T2U_TMS_BackWaterTemp_2 255 "无效" ;
VAL_ 2148892565 T2U_TMS_EnvTemp_2 255 "无效" ;
VAL_ 2148892565 M2P_TMS_OvrTmpLwFltLvl3_2_05 0 "制冷模式正常" 1 "环境温度超过55℃制冷保护或环境温度低于-40℃制冷保护" ;
VAL_ 2148892566 U2T_BMS_ControlMode_2 0 "关机模式" 1 "制冷模式" 2 "加热模式" 3 "自循环模式" ;
VAL_ 2148892566 T2U_TMS_RunState_2 0 "关机模式" 1 "制冷模式" 2 "加热模式" 3 "自循环模式" ;
VAL_ 2148892566 T2U_TMS_FaultCode_2 0 "无故障" ;
VAL_ 2148892566 T2U_TMS_FaultLevel_2 0 "无效" 1 "1级故障" 2 "2级故障" 3 "3级故障" ;
VAL_ 2148892566 U2T_BMS_TmptSetPoint_2 255 "Invalid" ;
VAL_ 2148892566 T2U_TMS_OutWaterTemp_2 255 "无效" ;
VAL_ 2148892566 T2U_TMS_BackWaterTemp_2 255 "无效" ;
VAL_ 2148892566 T2U_TMS_EnvTemp_2 255 "无效" ;
VAL_ 2148892566 M2P_TMS_OvrTmpLwFltLvl3_2_06 0 "制冷模式正常" 1 "环境温度超过55℃制冷保护或环境温度低于-40℃制冷保护" ;
VAL_ 2148892567 U2T_BMS_ControlMode_2 0 "关机模式" 1 "制冷模式" 2 "加热模式" 3 "自循环模式" ;
VAL_ 2148892567 T2U_TMS_RunState_2 0 "关机模式" 1 "制冷模式" 2 "加热模式" 3 "自循环模式" ;
VAL_ 2148892567 T2U_TMS_FaultCode_2 0 "无故障" ;
VAL_ 2148892567 T2U_TMS_FaultLevel_2 0 "无效" 1 "1级故障" 2 "2级故障" 3 "3级故障" ;
VAL_ 2148892567 U2T_BMS_TmptSetPoint_2 255 "Invalid" ;
VAL_ 2148892567 T2U_TMS_OutWaterTemp_2 255 "无效" ;
VAL_ 2148892567 T2U_TMS_BackWaterTemp_2 255 "无效" ;
VAL_ 2148892567 T2U_TMS_EnvTemp_2 255 "无效" ;
VAL_ 2148892567 M2P_TMS_OvrTmpLwFltLvl3_2_07 0 "制冷模式正常" 1 "环境温度超过55℃制冷保护或环境温度低于-40℃制冷保护" ;
VAL_ 2148892568 U2T_BMS_ControlMode_2 0 "关机模式" 1 "制冷模式" 2 "加热模式" 3 "自循环模式" ;
VAL_ 2148892568 T2U_TMS_RunState_2 0 "关机模式" 1 "制冷模式" 2 "加热模式" 3 "自循环模式" ;
VAL_ 2148892568 T2U_TMS_FaultCode_2 0 "无故障" ;
VAL_ 2148892568 T2U_TMS_FaultLevel_2 0 "无效" 1 "1级故障" 2 "2级故障" 3 "3级故障" ;
VAL_ 2148892568 U2T_BMS_TmptSetPoint_2 255 "Invalid" ;
VAL_ 2148892568 T2U_TMS_OutWaterTemp_2 255 "无效" ;
VAL_ 2148892568 T2U_TMS_BackWaterTemp_2 255 "无效" ;
VAL_ 2148892568 T2U_TMS_EnvTemp_2 255 "无效" ;
VAL_ 2148892568 M2P_TMS_OvrTmpLwFltLvl3_2_08 0 "制冷模式正常" 1 "环境温度超过55℃制冷保护或环境温度低于-40℃制冷保护" ;
VAL_ 2148892569 U2T_BMS_ControlMode_2 0 "关机模式" 1 "制冷模式" 2 "加热模式" 3 "自循环模式" ;
VAL_ 2148892569 T2U_TMS_RunState_2 0 "关机模式" 1 "制冷模式" 2 "加热模式" 3 "自循环模式" ;
VAL_ 2148892569 T2U_TMS_FaultCode_2 0 "无故障" ;
VAL_ 2148892569 T2U_TMS_FaultLevel_2 0 "无效" 1 "1级故障" 2 "2级故障" 3 "3级故障" ;
VAL_ 2148892569 U2T_BMS_TmptSetPoint_2 255 "Invalid" ;
VAL_ 2148892569 T2U_TMS_OutWaterTemp_2 255 "无效" ;
VAL_ 2148892569 T2U_TMS_BackWaterTemp_2 255 "无效" ;
VAL_ 2148892569 T2U_TMS_EnvTemp_2 255 "无效" ;
VAL_ 2148892569 M2P_TMS_OvrTmpLwFltLvl3_2_09 0 "制冷模式正常" 1 "环境温度超过55℃制冷保护或环境温度低于-40℃制冷保护" ;
VAL_ 2148892570 U2T_BMS_ControlMode_2 0 "关机模式" 1 "制冷模式" 2 "加热模式" 3 "自循环模式" ;
VAL_ 2148892570 T2U_TMS_RunState_2 0 "关机模式" 1 "制冷模式" 2 "加热模式" 3 "自循环模式" ;
VAL_ 2148892570 T2U_TMS_FaultCode_2 0 "无故障" ;
VAL_ 2148892570 T2U_TMS_FaultLevel_2 0 "无效" 1 "1级故障" 2 "2级故障" 3 "3级故障" ;
VAL_ 2148892570 U2T_BMS_TmptSetPoint_2 255 "Invalid" ;
VAL_ 2148892570 T2U_TMS_OutWaterTemp_2 255 "无效" ;
VAL_ 2148892570 T2U_TMS_BackWaterTemp_2 255 "无效" ;
VAL_ 2148892570 T2U_TMS_EnvTemp_2 255 "无效" ;
VAL_ 2148892570 M2P_TMS_OvrTmpLwFltLvl3_2_10 0 "制冷模式正常" 1 "环境温度超过55℃制冷保护或环境温度低于-40℃制冷保护" ;
VAL_ 2148892571 U2T_BMS_ControlMode_2 0 "关机模式" 1 "制冷模式" 2 "加热模式" 3 "自循环模式" ;
VAL_ 2148892571 T2U_TMS_RunState_2 0 "关机模式" 1 "制冷模式" 2 "加热模式" 3 "自循环模式" ;
VAL_ 2148892571 T2U_TMS_FaultCode_2 0 "无故障" ;
VAL_ 2148892571 T2U_TMS_FaultLevel_2 0 "无效" 1 "1级故障" 2 "2级故障" 3 "3级故障" ;
VAL_ 2148892571 U2T_BMS_TmptSetPoint_2 255 "Invalid" ;
VAL_ 2148892571 T2U_TMS_OutWaterTemp_2 255 "无效" ;
VAL_ 2148892571 T2U_TMS_BackWaterTemp_2 255 "无效" ;
VAL_ 2148892571 T2U_TMS_EnvTemp_2 255 "无效" ;
VAL_ 2148892571 M2P_TMS_OvrTmpLwFltLvl3_2_11 0 "制冷模式正常" 1 "环境温度超过55℃制冷保护或环境温度低于-40℃制冷保护" ;
VAL_ 2148892572 U2T_BMS_ControlMode_2 0 "关机模式" 1 "制冷模式" 2 "加热模式" 3 "自循环模式" ;
VAL_ 2148892572 T2U_TMS_RunState_2 0 "关机模式" 1 "制冷模式" 2 "加热模式" 3 "自循环模式" ;
VAL_ 2148892572 T2U_TMS_FaultCode_2 0 "无故障" ;
VAL_ 2148892572 T2U_TMS_FaultLevel_2 0 "无效" 1 "1级故障" 2 "2级故障" 3 "3级故障" ;
VAL_ 2148892572 U2T_BMS_TmptSetPoint_2 255 "Invalid" ;
VAL_ 2148892572 T2U_TMS_OutWaterTemp_2 255 "无效" ;
VAL_ 2148892572 T2U_TMS_BackWaterTemp_2 255 "无效" ;
VAL_ 2148892572 T2U_TMS_EnvTemp_2 255 "无效" ;
VAL_ 2148892572 M2P_TMS_OvrTmpLwFltLvl3_2_12 0 "制冷模式正常" 1 "环境温度超过55℃制冷保护或环境温度低于-40℃制冷保护" ;
VAL_ 2148892573 U2T_BMS_ControlMode_2 0 "关机模式" 1 "制冷模式" 2 "加热模式" 3 "自循环模式" ;
VAL_ 2148892573 T2U_TMS_RunState_2 0 "关机模式" 1 "制冷模式" 2 "加热模式" 3 "自循环模式" ;
VAL_ 2148892573 T2U_TMS_FaultCode_2 0 "无故障" ;
VAL_ 2148892573 T2U_TMS_FaultLevel_2 0 "无效" 1 "1级故障" 2 "2级故障" 3 "3级故障" ;
VAL_ 2148892573 U2T_BMS_TmptSetPoint_2 255 "Invalid" ;
VAL_ 2148892573 T2U_TMS_OutWaterTemp_2 255 "无效" ;
VAL_ 2148892573 T2U_TMS_BackWaterTemp_2 255 "无效" ;
VAL_ 2148892573 T2U_TMS_EnvTemp_2 255 "无效" ;
VAL_ 2148892573 M2P_TMS_OvrTmpLwFltLvl3_2_13 0 "制冷模式正常" 1 "环境温度超过55℃制冷保护或环境温度低于-40℃制冷保护" ;
VAL_ 2148892574 U2T_BMS_ControlMode_2 0 "关机模式" 1 "制冷模式" 2 "加热模式" 3 "自循环模式" ;
VAL_ 2148892574 T2U_TMS_RunState_2 0 "关机模式" 1 "制冷模式" 2 "加热模式" 3 "自循环模式" ;
VAL_ 2148892574 T2U_TMS_FaultCode_2 0 "无故障" ;
VAL_ 2148892574 T2U_TMS_FaultLevel_2 0 "无效" 1 "1级故障" 2 "2级故障" 3 "3级故障" ;
VAL_ 2148892574 U2T_BMS_TmptSetPoint_2 255 "Invalid" ;
VAL_ 2148892574 T2U_TMS_OutWaterTemp_2 255 "无效" ;
VAL_ 2148892574 T2U_TMS_BackWaterTemp_2 255 "无效" ;
VAL_ 2148892574 T2U_TMS_EnvTemp_2 255 "无效" ;
VAL_ 2148892574 M2P_TMS_OvrTmpLwFltLvl3_2_14 0 "制冷模式正常" 1 "环境温度超过55℃制冷保护或环境温度低于-40℃制冷保护" ;
VAL_ 2148892575 U2T_BMS_ControlMode_2 0 "关机模式" 1 "制冷模式" 2 "加热模式" 3 "自循环模式" ;
VAL_ 2148892575 T2U_TMS_RunState_2 0 "关机模式" 1 "制冷模式" 2 "加热模式" 3 "自循环模式" ;
VAL_ 2148892575 T2U_TMS_FaultCode_2 0 "无故障" ;
VAL_ 2148892575 T2U_TMS_FaultLevel_2 0 "无效" 1 "1级故障" 2 "2级故障" 3 "3级故障" ;
VAL_ 2148892575 U2T_BMS_TmptSetPoint_2 255 "Invalid" ;
VAL_ 2148892575 T2U_TMS_OutWaterTemp_2 255 "无效" ;
VAL_ 2148892575 T2U_TMS_BackWaterTemp_2 255 "无效" ;
VAL_ 2148892575 T2U_TMS_EnvTemp_2 255 "无效" ;
VAL_ 2148892575 M2P_TMS_OvrTmpLwFltLvl3_2_15 0 "制冷模式正常" 1 "环境温度超过55℃制冷保护或环境温度低于-40℃制冷保护" ;
VAL_ 2148892576 U2T_BMS_ControlMode_2 0 "关机模式" 1 "制冷模式" 2 "加热模式" 3 "自循环模式" ;
VAL_ 2148892576 T2U_TMS_RunState_2 0 "关机模式" 1 "制冷模式" 2 "加热模式" 3 "自循环模式" ;
VAL_ 2148892576 T2U_TMS_FaultCode_2 0 "无故障" ;
VAL_ 2148892576 T2U_TMS_FaultLevel_2 0 "无效" 1 "1级故障" 2 "2级故障" 3 "3级故障" ;
VAL_ 2148892576 U2T_BMS_TmptSetPoint_2 255 "Invalid" ;
VAL_ 2148892576 T2U_TMS_OutWaterTemp_2 255 "无效" ;
VAL_ 2148892576 T2U_TMS_BackWaterTemp_2 255 "无效" ;
VAL_ 2148892576 T2U_TMS_EnvTemp_2 255 "无效" ;
VAL_ 2148892576 M2P_TMS_OvrTmpLwFltLvl3_2_16 0 "制冷模式正常" 1 "环境温度超过55℃制冷保护或环境温度低于-40℃制冷保护" ;
VAL_ 2148892577 U2T_BMS_ControlMode_2 0 "关机模式" 1 "制冷模式" 2 "加热模式" 3 "自循环模式" ;
VAL_ 2148892577 T2U_TMS_RunState_2 0 "关机模式" 1 "制冷模式" 2 "加热模式" 3 "自循环模式" ;
VAL_ 2148892577 T2U_TMS_FaultCode_2 0 "无故障" ;
VAL_ 2148892577 T2U_TMS_FaultLevel_2 0 "无效" 1 "1级故障" 2 "2级故障" 3 "3级故障" ;
VAL_ 2148892577 U2T_BMS_TmptSetPoint_2 255 "Invalid" ;
VAL_ 2148892577 T2U_TMS_OutWaterTemp_2 255 "无效" ;
VAL_ 2148892577 T2U_TMS_BackWaterTemp_2 255 "无效" ;
VAL_ 2148892577 T2U_TMS_EnvTemp_2 255 "无效" ;
VAL_ 2148892577 M2P_TMS_OvrTmpLwFltLvl3_2_17 0 "制冷模式正常" 1 "环境温度超过55℃制冷保护或环境温度低于-40℃制冷保护" ;
VAL_ 2148892578 U2T_BMS_ControlMode_2 0 "关机模式" 1 "制冷模式" 2 "加热模式" 3 "自循环模式" ;
VAL_ 2148892578 T2U_TMS_RunState_2 0 "关机模式" 1 "制冷模式" 2 "加热模式" 3 "自循环模式" ;
VAL_ 2148892578 T2U_TMS_FaultCode_2 0 "无故障" ;
VAL_ 2148892578 T2U_TMS_FaultLevel_2 0 "无效" 1 "1级故障" 2 "2级故障" 3 "3级故障" ;
VAL_ 2148892578 U2T_BMS_TmptSetPoint_2 255 "Invalid" ;
VAL_ 2148892578 T2U_TMS_OutWaterTemp_2 255 "无效" ;
VAL_ 2148892578 T2U_TMS_BackWaterTemp_2 255 "无效" ;
VAL_ 2148892578 T2U_TMS_EnvTemp_2 255 "无效" ;
VAL_ 2148892578 M2P_TMS_OvrTmpLwFltLvl3_2_18 0 "制冷模式正常" 1 "环境温度超过55℃制冷保护或环境温度低于-40℃制冷保护" ;
VAL_ 2148892579 U2T_BMS_ControlMode_2 0 "关机模式" 1 "制冷模式" 2 "加热模式" 3 "自循环模式" ;
VAL_ 2148892579 T2U_TMS_RunState_2 0 "关机模式" 1 "制冷模式" 2 "加热模式" 3 "自循环模式" ;
VAL_ 2148892579 T2U_TMS_FaultCode_2 0 "无故障" ;
VAL_ 2148892579 T2U_TMS_FaultLevel_2 0 "无效" 1 "1级故障" 2 "2级故障" 3 "3级故障" ;
VAL_ 2148892579 U2T_BMS_TmptSetPoint_2 255 "Invalid" ;
VAL_ 2148892579 T2U_TMS_OutWaterTemp_2 255 "无效" ;
VAL_ 2148892579 T2U_TMS_BackWaterTemp_2 255 "无效" ;
VAL_ 2148892579 T2U_TMS_EnvTemp_2 255 "无效" ;
VAL_ 2148892579 M2P_TMS_OvrTmpLwFltLvl3_2_19 0 "制冷模式正常" 1 "环境温度超过55℃制冷保护或环境温度低于-40℃制冷保护" ;
VAL_ 2148892580 U2T_BMS_ControlMode_2 0 "关机模式" 1 "制冷模式" 2 "加热模式" 3 "自循环模式" ;
VAL_ 2148892580 T2U_TMS_RunState_2 0 "关机模式" 1 "制冷模式" 2 "加热模式" 3 "自循环模式" ;
VAL_ 2148892580 T2U_TMS_FaultCode_2 0 "无故障" ;
VAL_ 2148892580 T2U_TMS_FaultLevel_2 0 "无效" 1 "1级故障" 2 "2级故障" 3 "3级故障" ;
VAL_ 2148892580 U2T_BMS_TmptSetPoint_2 255 "Invalid" ;
VAL_ 2148892580 T2U_TMS_OutWaterTemp_2 255 "无效" ;
VAL_ 2148892580 T2U_TMS_BackWaterTemp_2 255 "无效" ;
VAL_ 2148892580 T2U_TMS_EnvTemp_2 255 "无效" ;
VAL_ 2148892580 M2P_TMS_OvrTmpLwFltLvl3_2_20 0 "制冷模式正常" 1 "环境温度超过55℃制冷保护或环境温度低于-40℃制冷保护" ;
VAL_ 2148892581 U2T_BMS_ControlMode_2 0 "关机模式" 1 "制冷模式" 2 "加热模式" 3 "自循环模式" ;
VAL_ 2148892581 T2U_TMS_RunState_2 0 "关机模式" 1 "制冷模式" 2 "加热模式" 3 "自循环模式" ;
VAL_ 2148892581 T2U_TMS_FaultCode_2 0 "无故障" ;
VAL_ 2148892581 T2U_TMS_FaultLevel_2 0 "无效" 1 "1级故障" 2 "2级故障" 3 "3级故障" ;
VAL_ 2148892581 U2T_BMS_TmptSetPoint_2 255 "Invalid" ;
VAL_ 2148892581 T2U_TMS_OutWaterTemp_2 255 "无效" ;
VAL_ 2148892581 T2U_TMS_BackWaterTemp_2 255 "无效" ;
VAL_ 2148892581 T2U_TMS_EnvTemp_2 255 "无效" ;
VAL_ 2148892581 M2P_TMS_OvrTmpLwFltLvl3_2_21 0 "制冷模式正常" 1 "环境温度超过55℃制冷保护或环境温度低于-40℃制冷保护" ;
VAL_ 2148892582 U2T_BMS_ControlMode_2 0 "关机模式" 1 "制冷模式" 2 "加热模式" 3 "自循环模式" ;
VAL_ 2148892582 T2U_TMS_RunState_2 0 "关机模式" 1 "制冷模式" 2 "加热模式" 3 "自循环模式" ;
VAL_ 2148892582 T2U_TMS_FaultCode_2 0 "无故障" ;
VAL_ 2148892582 T2U_TMS_FaultLevel_2 0 "无效" 1 "1级故障" 2 "2级故障" 3 "3级故障" ;
VAL_ 2148892582 U2T_BMS_TmptSetPoint_2 255 "Invalid" ;
VAL_ 2148892582 T2U_TMS_OutWaterTemp_2 255 "无效" ;
VAL_ 2148892582 T2U_TMS_BackWaterTemp_2 255 "无效" ;
VAL_ 2148892582 T2U_TMS_EnvTemp_2 255 "无效" ;
VAL_ 2148892582 M2P_TMS_OvrTmpLwFltLvl3_2_22 0 "制冷模式正常" 1 "环境温度超过55℃制冷保护或环境温度低于-40℃制冷保护" ;
VAL_ 2148892583 U2T_BMS_ControlMode_2 0 "关机模式" 1 "制冷模式" 2 "加热模式" 3 "自循环模式" ;
VAL_ 2148892583 T2U_TMS_RunState_2 0 "关机模式" 1 "制冷模式" 2 "加热模式" 3 "自循环模式" ;
VAL_ 2148892583 T2U_TMS_FaultCode_2 0 "无故障" ;
VAL_ 2148892583 T2U_TMS_FaultLevel_2 0 "无效" 1 "1级故障" 2 "2级故障" 3 "3级故障" ;
VAL_ 2148892583 U2T_BMS_TmptSetPoint_2 255 "Invalid" ;
VAL_ 2148892583 T2U_TMS_OutWaterTemp_2 255 "无效" ;
VAL_ 2148892583 T2U_TMS_BackWaterTemp_2 255 "无效" ;
VAL_ 2148892583 T2U_TMS_EnvTemp_2 255 "无效" ;
VAL_ 2148892583 M2P_TMS_OvrTmpLwFltLvl3_2_23 0 "制冷模式正常" 1 "环境温度超过55℃制冷保护或环境温度低于-40℃制冷保护" ;
VAL_ 2148892584 U2T_BMS_ControlMode_2 0 "关机模式" 1 "制冷模式" 2 "加热模式" 3 "自循环模式" ;
VAL_ 2148892584 T2U_TMS_RunState_2 0 "关机模式" 1 "制冷模式" 2 "加热模式" 3 "自循环模式" ;
VAL_ 2148892584 T2U_TMS_FaultCode_2 0 "无故障" ;
VAL_ 2148892584 T2U_TMS_FaultLevel_2 0 "无效" 1 "1级故障" 2 "2级故障" 3 "3级故障" ;
VAL_ 2148892584 U2T_BMS_TmptSetPoint_2 255 "Invalid" ;
VAL_ 2148892584 T2U_TMS_OutWaterTemp_2 255 "无效" ;
VAL_ 2148892584 T2U_TMS_BackWaterTemp_2 255 "无效" ;
VAL_ 2148892584 T2U_TMS_EnvTemp_2 255 "无效" ;
VAL_ 2148892584 M2P_TMS_OvrTmpLwFltLvl3_2_24 0 "制冷模式正常" 1 "环境温度超过55℃制冷保护或环境温度低于-40℃制冷保护" ;
VAL_ 2148892585 U2T_BMS_ControlMode_2 0 "关机模式" 1 "制冷模式" 2 "加热模式" 3 "自循环模式" ;
VAL_ 2148892585 T2U_TMS_RunState_2 0 "关机模式" 1 "制冷模式" 2 "加热模式" 3 "自循环模式" ;
VAL_ 2148892585 T2U_TMS_FaultCode_2 0 "无故障" ;
VAL_ 2148892585 T2U_TMS_FaultLevel_2 0 "无效" 1 "1级故障" 2 "2级故障" 3 "3级故障" ;
VAL_ 2148892585 U2T_BMS_TmptSetPoint_2 255 "Invalid" ;
VAL_ 2148892585 T2U_TMS_OutWaterTemp_2 255 "无效" ;
VAL_ 2148892585 T2U_TMS_BackWaterTemp_2 255 "无效" ;
VAL_ 2148892585 T2U_TMS_EnvTemp_2 255 "无效" ;
VAL_ 2148892585 M2P_TMS_OvrTmpLwFltLvl3_2_25 0 "制冷模式正常" 1 "环境温度超过55℃制冷保护或环境温度低于-40℃制冷保护" ;
VAL_ 2148892586 U2T_BMS_ControlMode_2 0 "关机模式" 1 "制冷模式" 2 "加热模式" 3 "自循环模式" ;
VAL_ 2148892586 T2U_TMS_RunState_2 0 "关机模式" 1 "制冷模式" 2 "加热模式" 3 "自循环模式" ;
VAL_ 2148892586 T2U_TMS_FaultCode_2 0 "无故障" ;
VAL_ 2148892586 T2U_TMS_FaultLevel_2 0 "无效" 1 "1级故障" 2 "2级故障" 3 "3级故障" ;
VAL_ 2148892586 U2T_BMS_TmptSetPoint_2 255 "Invalid" ;
VAL_ 2148892586 T2U_TMS_OutWaterTemp_2 255 "无效" ;
VAL_ 2148892586 T2U_TMS_BackWaterTemp_2 255 "无效" ;
VAL_ 2148892586 T2U_TMS_EnvTemp_2 255 "无效" ;
VAL_ 2148892586 M2P_TMS_OvrTmpLwFltLvl3_2_26 0 "制冷模式正常" 1 "环境温度超过55℃制冷保护或环境温度低于-40℃制冷保护" ;
VAL_ 2148892587 U2T_BMS_ControlMode_2 0 "关机模式" 1 "制冷模式" 2 "加热模式" 3 "自循环模式" ;
VAL_ 2148892587 T2U_TMS_RunState_2 0 "关机模式" 1 "制冷模式" 2 "加热模式" 3 "自循环模式" ;
VAL_ 2148892587 T2U_TMS_FaultCode_2 0 "无故障" ;
VAL_ 2148892587 T2U_TMS_FaultLevel_2 0 "无效" 1 "1级故障" 2 "2级故障" 3 "3级故障" ;
VAL_ 2148892587 U2T_BMS_TmptSetPoint_2 255 "Invalid" ;
VAL_ 2148892587 T2U_TMS_OutWaterTemp_2 255 "无效" ;
VAL_ 2148892587 T2U_TMS_BackWaterTemp_2 255 "无效" ;
VAL_ 2148892587 T2U_TMS_EnvTemp_2 255 "无效" ;
VAL_ 2148892587 M2P_TMS_OvrTmpLwFltLvl3_2_27 0 "制冷模式正常" 1 "环境温度超过55℃制冷保护或环境温度低于-40℃制冷保护" ;
VAL_ 2148892588 U2T_BMS_ControlMode_2 0 "关机模式" 1 "制冷模式" 2 "加热模式" 3 "自循环模式" ;
VAL_ 2148892588 T2U_TMS_RunState_2 0 "关机模式" 1 "制冷模式" 2 "加热模式" 3 "自循环模式" ;
VAL_ 2148892588 T2U_TMS_FaultCode_2 0 "无故障" ;
VAL_ 2148892588 T2U_TMS_FaultLevel_2 0 "无效" 1 "1级故障" 2 "2级故障" 3 "3级故障" ;
VAL_ 2148892588 U2T_BMS_TmptSetPoint_2 255 "Invalid" ;
VAL_ 2148892588 T2U_TMS_OutWaterTemp_2 255 "无效" ;
VAL_ 2148892588 T2U_TMS_BackWaterTemp_2 255 "无效" ;
VAL_ 2148892588 T2U_TMS_EnvTemp_2 255 "无效" ;
VAL_ 2148892588 M2P_TMS_OvrTmpLwFltLvl3_2_28 0 "制冷模式正常" 1 "环境温度超过55℃制冷保护或环境温度低于-40℃制冷保护" ;
VAL_ 2148892589 U2T_BMS_ControlMode_2 0 "关机模式" 1 "制冷模式" 2 "加热模式" 3 "自循环模式" ;
VAL_ 2148892589 T2U_TMS_RunState_2 0 "关机模式" 1 "制冷模式" 2 "加热模式" 3 "自循环模式" ;
VAL_ 2148892589 T2U_TMS_FaultCode_2 0 "无故障" ;
VAL_ 2148892589 T2U_TMS_FaultLevel_2 0 "无效" 1 "1级故障" 2 "2级故障" 3 "3级故障" ;
VAL_ 2148892589 U2T_BMS_TmptSetPoint_2 255 "Invalid" ;
VAL_ 2148892589 T2U_TMS_OutWaterTemp_2 255 "无效" ;
VAL_ 2148892589 T2U_TMS_BackWaterTemp_2 255 "无效" ;
VAL_ 2148892589 T2U_TMS_EnvTemp_2 255 "无效" ;
VAL_ 2148892589 M2P_TMS_OvrTmpLwFltLvl3_2_29 0 "制冷模式正常" 1 "环境温度超过55℃制冷保护或环境温度低于-40℃制冷保护" ;
VAL_ 2148892590 U2T_BMS_ControlMode_2 0 "关机模式" 1 "制冷模式" 2 "加热模式" 3 "自循环模式" ;
VAL_ 2148892590 T2U_TMS_RunState_2 0 "关机模式" 1 "制冷模式" 2 "加热模式" 3 "自循环模式" ;
VAL_ 2148892590 T2U_TMS_FaultCode_2 0 "无故障" ;
VAL_ 2148892590 T2U_TMS_FaultLevel_2 0 "无效" 1 "1级故障" 2 "2级故障" 3 "3级故障" ;
VAL_ 2148892590 U2T_BMS_TmptSetPoint_2 255 "Invalid" ;
VAL_ 2148892590 T2U_TMS_OutWaterTemp_2 255 "无效" ;
VAL_ 2148892590 T2U_TMS_BackWaterTemp_2 255 "无效" ;
VAL_ 2148892590 T2U_TMS_EnvTemp_2 255 "无效" ;
VAL_ 2148892590 M2P_TMS_OvrTmpLwFltLvl3_2_30 0 "制冷模式正常" 1 "环境温度超过55℃制冷保护或环境温度低于-40℃制冷保护" ;
VAL_ 2148892591 U2T_BMS_ControlMode_2 0 "关机模式" 1 "制冷模式" 2 "加热模式" 3 "自循环模式" ;
VAL_ 2148892591 T2U_TMS_RunState_2 0 "关机模式" 1 "制冷模式" 2 "加热模式" 3 "自循环模式" ;
VAL_ 2148892591 T2U_TMS_FaultCode_2 0 "无故障" ;
VAL_ 2148892591 T2U_TMS_FaultLevel_2 0 "无效" 1 "1级故障" 2 "2级故障" 3 "3级故障" ;
VAL_ 2148892591 U2T_BMS_TmptSetPoint_2 255 "Invalid" ;
VAL_ 2148892591 T2U_TMS_OutWaterTemp_2 255 "无效" ;
VAL_ 2148892591 T2U_TMS_BackWaterTemp_2 255 "无效" ;
VAL_ 2148892591 T2U_TMS_EnvTemp_2 255 "无效" ;
VAL_ 2148892591 M2P_TMS_OvrTmpLwFltLvl3_2_31 0 "制冷模式正常" 1 "环境温度超过55℃制冷保护或环境温度低于-40℃制冷保护" ;
VAL_ 2349461137 IsoFault 0 "No fault" 1 "fault Occur" ;
VAL_ 2349461137 M2M_SUMDATA1_Reserved 0 "No fault" 1 "fault Occur" ;
VAL_ 2149023633 RTC_CMD 0 "Reserved" 1 "Write RTC" 2 "Read RTC" ;
VAL_ 2149023634 RTC_CMD 0 "Reserved" 1 "Write RTC" 2 "Read RTC" ;
VAL_ 2149023635 RTC_CMD 0 "Reserved" 1 "Write RTC" 2 "Read RTC" ;
VAL_ 2149023636 RTC_CMD 0 "Reserved" 1 "Write RTC" 2 "Read RTC" ;
VAL_ 2149023637 RTC_CMD 0 "Reserved" 1 "Write RTC" 2 "Read RTC" ;
VAL_ 2149023638 RTC_CMD 0 "Reserved" 1 "Write RTC" 2 "Read RTC" ;
VAL_ 2149023639 RTC_CMD 0 "Reserved" 1 "Write RTC" 2 "Read RTC" ;
VAL_ 2149023640 RTC_CMD 0 "Reserved" 1 "Write RTC" 2 "Read RTC" ;
VAL_ 2149023641 RTC_CMD 0 "Reserved" 1 "Write RTC" 2 "Read RTC" ;
VAL_ 2149023642 RTC_CMD 0 "Reserved" 1 "Write RTC" 2 "Read RTC" ;
VAL_ 2149023643 RTC_CMD 0 "Reserved" 1 "Write RTC" 2 "Read RTC" ;
VAL_ 2149023644 RTC_CMD 0 "Reserved" 1 "Write RTC" 2 "Read RTC" ;
VAL_ 2149023645 RTC_CMD 0 "Reserved" 1 "Write RTC" 2 "Read RTC" ;
VAL_ 2149023646 RTC_CMD 0 "Reserved" 1 "Write RTC" 2 "Read RTC" ;
VAL_ 2149023647 RTC_CMD 0 "Reserved" 1 "Write RTC" 2 "Read RTC" ;
VAL_ 2149023648 RTC_CMD 0 "Reserved" 1 "Write RTC" 2 "Read RTC" ;
VAL_ 2149023649 RTC_CMD 0 "Reserved" 1 "Write RTC" 2 "Read RTC" ;
VAL_ 2149023650 RTC_CMD 0 "Reserved" 1 "Write RTC" 2 "Read RTC" ;
VAL_ 2149023651 RTC_CMD 0 "Reserved" 1 "Write RTC" 2 "Read RTC" ;
VAL_ 2149023652 RTC_CMD 0 "Reserved" 1 "Write RTC" 2 "Read RTC" ;
VAL_ 2149023653 RTC_CMD 0 "Reserved" 1 "Write RTC" 2 "Read RTC" ;
VAL_ 2149023654 RTC_CMD 0 "Reserved" 1 "Write RTC" 2 "Read RTC" ;
VAL_ 2149023655 RTC_CMD 0 "Reserved" 1 "Write RTC" 2 "Read RTC" ;
VAL_ 2149023656 RTC_CMD 0 "Reserved" 1 "Write RTC" 2 "Read RTC" ;
VAL_ 2149023657 RTC_CMD 0 "Reserved" 1 "Write RTC" 2 "Read RTC" ;
VAL_ 2149023658 RTC_CMD 0 "Reserved" 1 "Write RTC" 2 "Read RTC" ;
VAL_ 2149023659 RTC_CMD 0 "Reserved" 1 "Write RTC" 2 "Read RTC" ;
VAL_ 2149023660 RTC_CMD 0 "Reserved" 1 "Write RTC" 2 "Read RTC" ;
VAL_ 2149023661 RTC_CMD 0 "Reserved" 1 "Write RTC" 2 "Read RTC" ;
VAL_ 2149023662 RTC_CMD 0 "Reserved" 1 "Write RTC" 2 "Read RTC" ;
VAL_ 2149023663 RTC_CMD 0 "Reserved" 1 "Write RTC" 2 "Read RTC" ;
VERSION ""

NS_ :

BS_:

BU_: MBMU PC SBMU IMM ETH DCDC LEMS

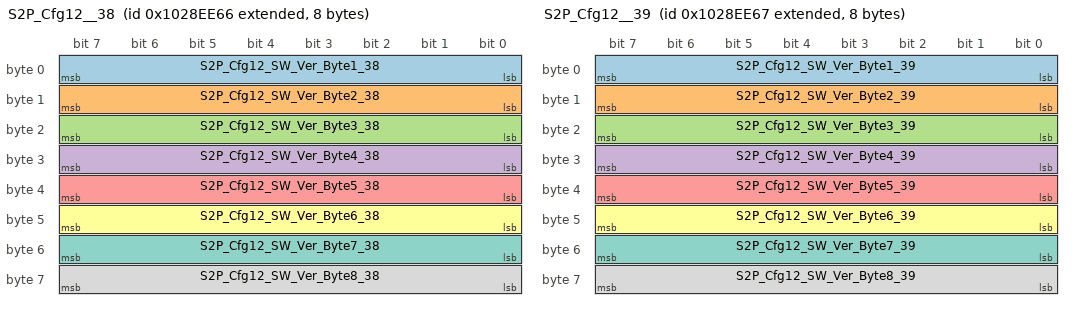
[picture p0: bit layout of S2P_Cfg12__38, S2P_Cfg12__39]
BO_ 2418601574 S2P_Cfg12__38: 8 SBMU
 SG_ S2P_Cfg12_SW_Ver_Byte1_38 : 0|8@1+ (1,0) [0|255] ""  PC
 SG_ S2P_Cfg12_SW_Ver_Byte2_38 : 8|8@1+ (1,0) [0|255] ""  PC
 SG_ S2P_Cfg12_SW_Ver_Byte3_38 : 16|8@1+ (1,0) [0|255] ""  PC
 SG_ S2P_Cfg12_SW_Ver_Byte4_38 : 24|8@1+ (1,0) [0|255] ""  PC
 SG_ S2P_Cfg12_SW_Ver_Byte5_38 : 32|8@1+ (1,0) [0|255] ""  PC
 SG_ S2P_Cfg12_SW_Ver_Byte6_38 : 40|8@1+ (1,0) [0|255] ""  PC
 SG_ S2P_Cfg12_SW_Ver_Byte7_38 : 48|8@1+ (1,0) [0|255] ""  PC
 SG_ S2P_Cfg12_SW_Ver_Byte8_38 : 56|8@1+ (1,0) [0|255] ""  PC

BO_ 2418601575 S2P_Cfg12__39: 8 SBMU
 SG_ S2P_Cfg12_SW_Ver_Byte1_39 : 0|8@1+ (1,0) [0|255] ""  PC
 SG_ S2P_Cfg12_SW_Ver_Byte2_39 : 8|8@1+ (1,0) [0|255] ""  PC
 SG_ S2P_Cfg12_SW_Ver_Byte3_39 : 16|8@1+ (1,0) [0|255] ""  PC
 SG_ S2P_Cfg12_SW_Ver_Byte4_39 : 24|8@1+ (1,0) [0|255] ""  PC
 SG_ S2P_Cfg12_SW_Ver_Byte5_39 : 32|8@1+ (1,0) [0|255] ""  PC
 SG_ S2P_Cfg12_SW_Ver_Byte6_39 : 40|8@1+ (1,0) [0|255] ""  PC
 SG_ S2P_Cfg12_SW_Ver_Byte7_39 : 48|8@1+ (1,0) [0|255] ""  PC
 SG_ S2P_Cfg12_SW_Ver_Byte8_39 : 56|8@1+ (1,0) [0|255] ""  PC

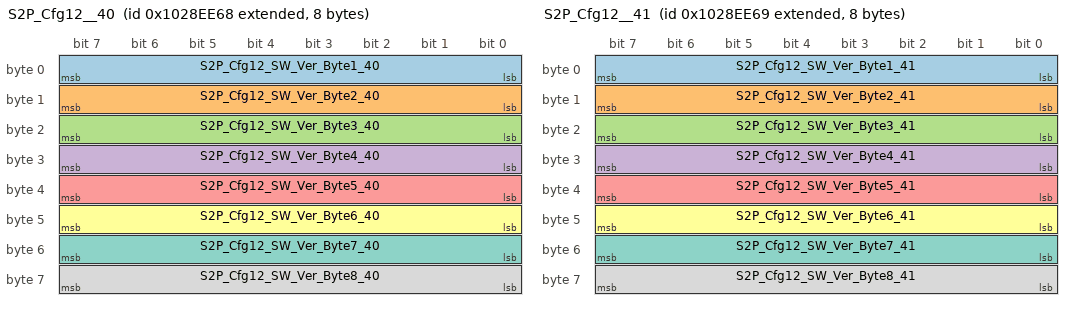
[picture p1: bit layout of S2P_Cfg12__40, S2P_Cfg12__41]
BO_ 2418601576 S2P_Cfg12__40: 8 SBMU
 SG_ S2P_Cfg12_SW_Ver_Byte1_40 : 0|8@1+ (1,0) [0|255] ""  PC
 SG_ S2P_Cfg12_SW_Ver_Byte2_40 : 8|8@1+ (1,0) [0|255] ""  PC
 SG_ S2P_Cfg12_SW_Ver_Byte3_40 : 16|8@1+ (1,0) [0|255] ""  PC
 SG_ S2P_Cfg12_SW_Ver_Byte4_40 : 24|8@1+ (1,0) [0|255] ""  PC
 SG_ S2P_Cfg12_SW_Ver_Byte5_40 : 32|8@1+ (1,0) [0|255] ""  PC
 SG_ S2P_Cfg12_SW_Ver_Byte6_40 : 40|8@1+ (1,0) [0|255] ""  PC
 SG_ S2P_Cfg12_SW_Ver_Byte7_40 : 48|8@1+ (1,0) [0|255] ""  PC
 SG_ S2P_Cfg12_SW_Ver_Byte8_40 : 56|8@1+ (1,0) [0|255] ""  PC

BO_ 2418601577 S2P_Cfg12__41: 8 SBMU
 SG_ S2P_Cfg12_SW_Ver_Byte1_41 : 0|8@1+ (1,0) [0|255] ""  PC
 SG_ S2P_Cfg12_SW_Ver_Byte2_41 : 8|8@1+ (1,0) [0|255] ""  PC
 SG_ S2P_Cfg12_SW_Ver_Byte3_41 : 16|8@1+ (1,0) [0|255] ""  PC
 SG_ S2P_Cfg12_SW_Ver_Byte4_41 : 24|8@1+ (1,0) [0|255] ""  PC
 SG_ S2P_Cfg12_SW_Ver_Byte5_41 : 32|8@1+ (1,0) [0|255] ""  PC
 SG_ S2P_Cfg12_SW_Ver_Byte6_41 : 40|8@1+ (1,0) [0|255] ""  PC
 SG_ S2P_Cfg12_SW_Ver_Byte7_41 : 48|8@1+ (1,0) [0|255] ""  PC
 SG_ S2P_Cfg12_SW_Ver_Byte8_41 : 56|8@1+ (1,0) [0|255] ""  PC

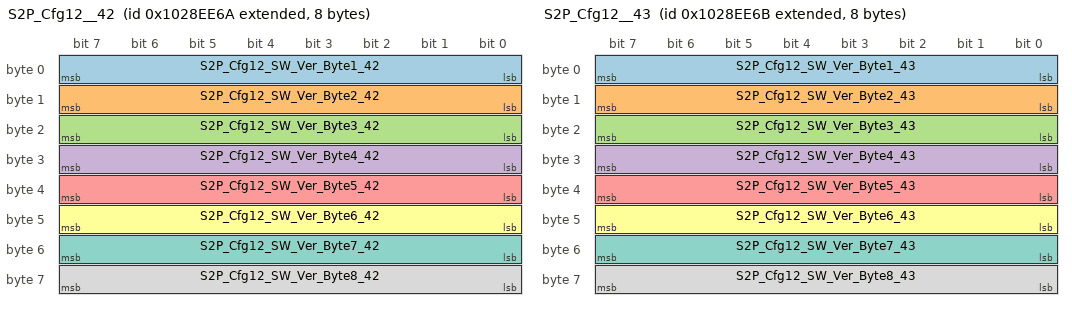
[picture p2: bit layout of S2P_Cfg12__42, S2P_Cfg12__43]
BO_ 2418601578 S2P_Cfg12__42: 8 SBMU
 SG_ S2P_Cfg12_SW_Ver_Byte1_42 : 0|8@1+ (1,0) [0|255] ""  PC
 SG_ S2P_Cfg12_SW_Ver_Byte2_42 : 8|8@1+ (1,0) [0|255] ""  PC
 SG_ S2P_Cfg12_SW_Ver_Byte3_42 : 16|8@1+ (1,0) [0|255] ""  PC
 SG_ S2P_Cfg12_SW_Ver_Byte4_42 : 24|8@1+ (1,0) [0|255] ""  PC
 SG_ S2P_Cfg12_SW_Ver_Byte5_42 : 32|8@1+ (1,0) [0|255] ""  PC
 SG_ S2P_Cfg12_SW_Ver_Byte6_42 : 40|8@1+ (1,0) [0|255] ""  PC
 SG_ S2P_Cfg12_SW_Ver_Byte7_42 : 48|8@1+ (1,0) [0|255] ""  PC
 SG_ S2P_Cfg12_SW_Ver_Byte8_42 : 56|8@1+ (1,0) [0|255] ""  PC

BO_ 2418601579 S2P_Cfg12__43: 8 SBMU
 SG_ S2P_Cfg12_SW_Ver_Byte1_43 : 0|8@1+ (1,0) [0|255] ""  PC
 SG_ S2P_Cfg12_SW_Ver_Byte2_43 : 8|8@1+ (1,0) [0|255] ""  PC
 SG_ S2P_Cfg12_SW_Ver_Byte3_43 : 16|8@1+ (1,0) [0|255] ""  PC
 SG_ S2P_Cfg12_SW_Ver_Byte4_43 : 24|8@1+ (1,0) [0|255] ""  PC
 SG_ S2P_Cfg12_SW_Ver_Byte5_43 : 32|8@1+ (1,0) [0|255] ""  PC
 SG_ S2P_Cfg12_SW_Ver_Byte6_43 : 40|8@1+ (1,0) [0|255] ""  PC
 SG_ S2P_Cfg12_SW_Ver_Byte7_43 : 48|8@1+ (1,0) [0|255] ""  PC
 SG_ S2P_Cfg12_SW_Ver_Byte8_43 : 56|8@1+ (1,0) [0|255] ""  PC

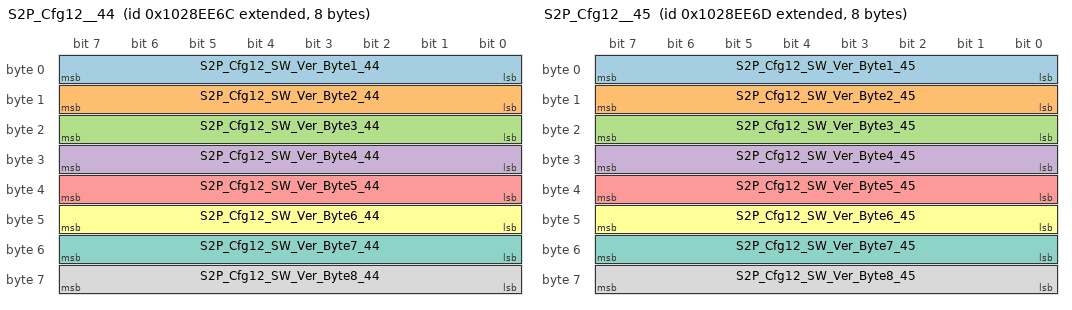
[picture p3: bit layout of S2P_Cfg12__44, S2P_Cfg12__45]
BO_ 2418601580 S2P_Cfg12__44: 8 SBMU
 SG_ S2P_Cfg12_SW_Ver_Byte1_44 : 0|8@1+ (1,0) [0|255] ""  PC
 SG_ S2P_Cfg12_SW_Ver_Byte2_44 : 8|8@1+ (1,0) [0|255] ""  PC
 SG_ S2P_Cfg12_SW_Ver_Byte3_44 : 16|8@1+ (1,0) [0|255] ""  PC
 SG_ S2P_Cfg12_SW_Ver_Byte4_44 : 24|8@1+ (1,0) [0|255] ""  PC
 SG_ S2P_Cfg12_SW_Ver_Byte5_44 : 32|8@1+ (1,0) [0|255] ""  PC
 SG_ S2P_Cfg12_SW_Ver_Byte6_44 : 40|8@1+ (1,0) [0|255] ""  PC
 SG_ S2P_Cfg12_SW_Ver_Byte7_44 : 48|8@1+ (1,0) [0|255] ""  PC
 SG_ S2P_Cfg12_SW_Ver_Byte8_44 : 56|8@1+ (1,0) [0|255] ""  PC

BO_ 2418601581 S2P_Cfg12__45: 8 SBMU
 SG_ S2P_Cfg12_SW_Ver_Byte1_45 : 0|8@1+ (1,0) [0|255] ""  PC
 SG_ S2P_Cfg12_SW_Ver_Byte2_45 : 8|8@1+ (1,0) [0|255] ""  PC
 SG_ S2P_Cfg12_SW_Ver_Byte3_45 : 16|8@1+ (1,0) [0|255] ""  PC
 SG_ S2P_Cfg12_SW_Ver_Byte4_45 : 24|8@1+ (1,0) [0|255] ""  PC
 SG_ S2P_Cfg12_SW_Ver_Byte5_45 : 32|8@1+ (1,0) [0|255] ""  PC
 SG_ S2P_Cfg12_SW_Ver_Byte6_45 : 40|8@1+ (1,0) [0|255] ""  PC
 SG_ S2P_Cfg12_SW_Ver_Byte7_45 : 48|8@1+ (1,0) [0|255] ""  PC
 SG_ S2P_Cfg12_SW_Ver_Byte8_45 : 56|8@1+ (1,0) [0|255] ""  PC

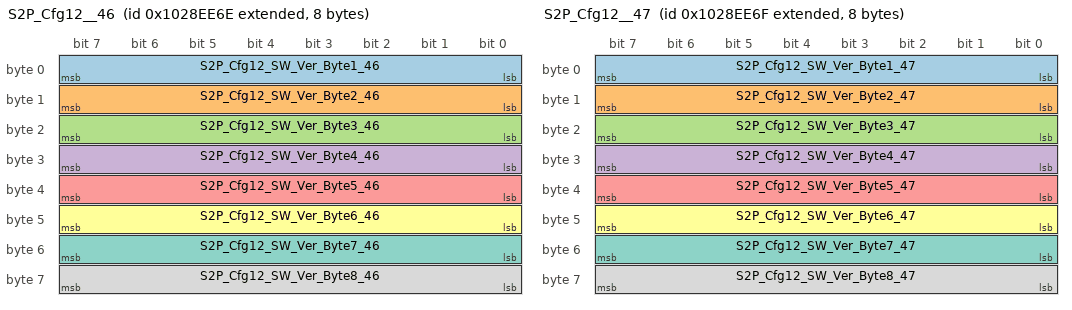
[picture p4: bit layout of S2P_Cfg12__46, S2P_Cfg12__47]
BO_ 2418601582 S2P_Cfg12__46: 8 SBMU
 SG_ S2P_Cfg12_SW_Ver_Byte1_46 : 0|8@1+ (1,0) [0|255] ""  PC
 SG_ S2P_Cfg12_SW_Ver_Byte2_46 : 8|8@1+ (1,0) [0|255] ""  PC
 SG_ S2P_Cfg12_SW_Ver_Byte3_46 : 16|8@1+ (1,0) [0|255] ""  PC
 SG_ S2P_Cfg12_SW_Ver_Byte4_46 : 24|8@1+ (1,0) [0|255] ""  PC
 SG_ S2P_Cfg12_SW_Ver_Byte5_46 : 32|8@1+ (1,0) [0|255] ""  PC
 SG_ S2P_Cfg12_SW_Ver_Byte6_46 : 40|8@1+ (1,0) [0|255] ""  PC
 SG_ S2P_Cfg12_SW_Ver_Byte7_46 : 48|8@1+ (1,0) [0|255] ""  PC
 SG_ S2P_Cfg12_SW_Ver_Byte8_46 : 56|8@1+ (1,0) [0|255] ""  PC

BO_ 2418601583 S2P_Cfg12__47: 8 SBMU
 SG_ S2P_Cfg12_SW_Ver_Byte1_47 : 0|8@1+ (1,0) [0|255] ""  PC
 SG_ S2P_Cfg12_SW_Ver_Byte2_47 : 8|8@1+ (1,0) [0|255] ""  PC
 SG_ S2P_Cfg12_SW_Ver_Byte3_47 : 16|8@1+ (1,0) [0|255] ""  PC
 SG_ S2P_Cfg12_SW_Ver_Byte4_47 : 24|8@1+ (1,0) [0|255] ""  PC
 SG_ S2P_Cfg12_SW_Ver_Byte5_47 : 32|8@1+ (1,0) [0|255] ""  PC
 SG_ S2P_Cfg12_SW_Ver_Byte6_47 : 40|8@1+ (1,0) [0|255] ""  PC
 SG_ S2P_Cfg12_SW_Ver_Byte7_47 : 48|8@1+ (1,0) [0|255] ""  PC
 SG_ S2P_Cfg12_SW_Ver_Byte8_47 : 56|8@1+ (1,0) [0|255] ""  PC

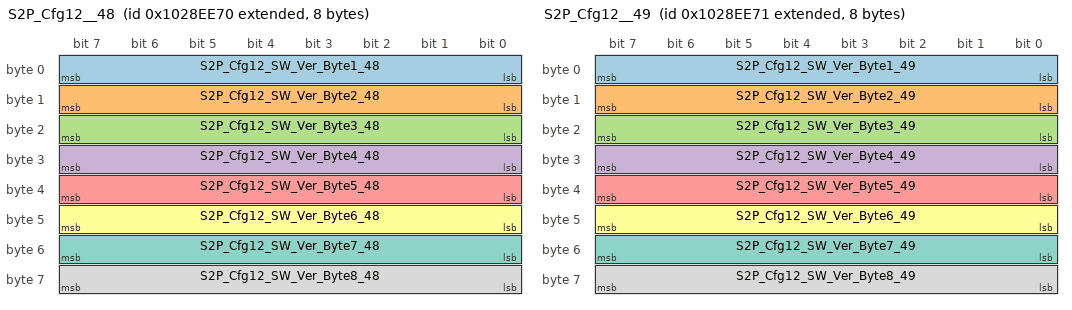
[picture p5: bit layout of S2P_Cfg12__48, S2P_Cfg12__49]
BO_ 2418601584 S2P_Cfg12__48: 8 SBMU
 SG_ S2P_Cfg12_SW_Ver_Byte1_48 : 0|8@1+ (1,0) [0|255] ""  PC
 SG_ S2P_Cfg12_SW_Ver_Byte2_48 : 8|8@1+ (1,0) [0|255] ""  PC
 SG_ S2P_Cfg12_SW_Ver_Byte3_48 : 16|8@1+ (1,0) [0|255] ""  PC
 SG_ S2P_Cfg12_SW_Ver_Byte4_48 : 24|8@1+ (1,0) [0|255] ""  PC
 SG_ S2P_Cfg12_SW_Ver_Byte5_48 : 32|8@1+ (1,0) [0|255] ""  PC
 SG_ S2P_Cfg12_SW_Ver_Byte6_48 : 40|8@1+ (1,0) [0|255] ""  PC
 SG_ S2P_Cfg12_SW_Ver_Byte7_48 : 48|8@1+ (1,0) [0|255] ""  PC
 SG_ S2P_Cfg12_SW_Ver_Byte8_48 : 56|8@1+ (1,0) [0|255] ""  PC

BO_ 2418601585 S2P_Cfg12__49: 8 SBMU
 SG_ S2P_Cfg12_SW_Ver_Byte1_49 : 0|8@1+ (1,0) [0|255] ""  PC
 SG_ S2P_Cfg12_SW_Ver_Byte2_49 : 8|8@1+ (1,0) [0|255] ""  PC
 SG_ S2P_Cfg12_SW_Ver_Byte3_49 : 16|8@1+ (1,0) [0|255] ""  PC
 SG_ S2P_Cfg12_SW_Ver_Byte4_49 : 24|8@1+ (1,0) [0|255] ""  PC
 SG_ S2P_Cfg12_SW_Ver_Byte5_49 : 32|8@1+ (1,0) [0|255] ""  PC
 SG_ S2P_Cfg12_SW_Ver_Byte6_49 : 40|8@1+ (1,0) [0|255] ""  PC
 SG_ S2P_Cfg12_SW_Ver_Byte7_49 : 48|8@1+ (1,0) [0|255] ""  PC
 SG_ S2P_Cfg12_SW_Ver_Byte8_49 : 56|8@1+ (1,0) [0|255] ""  PC

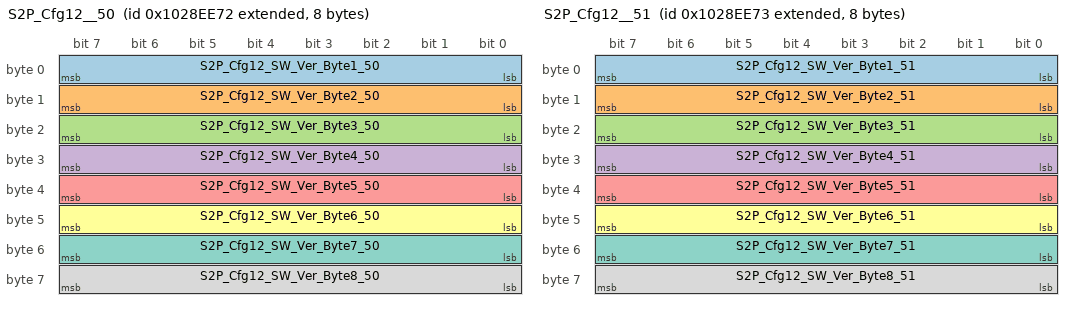
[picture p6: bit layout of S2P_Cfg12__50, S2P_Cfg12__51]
BO_ 2418601586 S2P_Cfg12__50: 8 SBMU
 SG_ S2P_Cfg12_SW_Ver_Byte1_50 : 0|8@1+ (1,0) [0|255] ""  PC
 SG_ S2P_Cfg12_SW_Ver_Byte2_50 : 8|8@1+ (1,0) [0|255] ""  PC
 SG_ S2P_Cfg12_SW_Ver_Byte3_50 : 16|8@1+ (1,0) [0|255] ""  PC
 SG_ S2P_Cfg12_SW_Ver_Byte4_50 : 24|8@1+ (1,0) [0|255] ""  PC
 SG_ S2P_Cfg12_SW_Ver_Byte5_50 : 32|8@1+ (1,0) [0|255] ""  PC
 SG_ S2P_Cfg12_SW_Ver_Byte6_50 : 40|8@1+ (1,0) [0|255] ""  PC
 SG_ S2P_Cfg12_SW_Ver_Byte7_50 : 48|8@1+ (1,0) [0|255] ""  PC
 SG_ S2P_Cfg12_SW_Ver_Byte8_50 : 56|8@1+ (1,0) [0|255] ""  PC

BO_ 2418601587 S2P_Cfg12__51: 8 SBMU
 SG_ S2P_Cfg12_SW_Ver_Byte1_51 : 0|8@1+ (1,0) [0|255] ""  PC
 SG_ S2P_Cfg12_SW_Ver_Byte2_51 : 8|8@1+ (1,0) [0|255] ""  PC
 SG_ S2P_Cfg12_SW_Ver_Byte3_51 : 16|8@1+ (1,0) [0|255] ""  PC
 SG_ S2P_Cfg12_SW_Ver_Byte4_51 : 24|8@1+ (1,0) [0|255] ""  PC
 SG_ S2P_Cfg12_SW_Ver_Byte5_51 : 32|8@1+ (1,0) [0|255] ""  PC
 SG_ S2P_Cfg12_SW_Ver_Byte6_51 : 40|8@1+ (1,0) [0|255] ""  PC
 SG_ S2P_Cfg12_SW_Ver_Byte7_51 : 48|8@1+ (1,0) [0|255] ""  PC
 SG_ S2P_Cfg12_SW_Ver_Byte8_51 : 56|8@1+ (1,0) [0|255] ""  PC

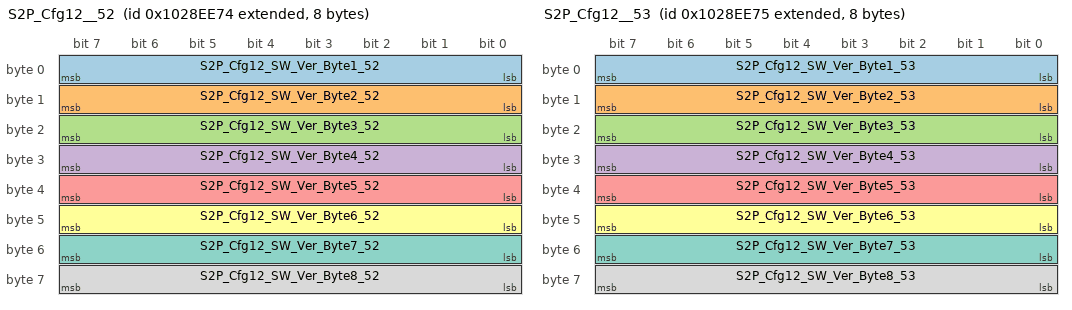
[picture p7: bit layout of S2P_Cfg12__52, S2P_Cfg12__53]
BO_ 2418601588 S2P_Cfg12__52: 8 SBMU
 SG_ S2P_Cfg12_SW_Ver_Byte1_52 : 0|8@1+ (1,0) [0|255] ""  PC
 SG_ S2P_Cfg12_SW_Ver_Byte2_52 : 8|8@1+ (1,0) [0|255] ""  PC
 SG_ S2P_Cfg12_SW_Ver_Byte3_52 : 16|8@1+ (1,0) [0|255] ""  PC
 SG_ S2P_Cfg12_SW_Ver_Byte4_52 : 24|8@1+ (1,0) [0|255] ""  PC
 SG_ S2P_Cfg12_SW_Ver_Byte5_52 : 32|8@1+ (1,0) [0|255] ""  PC
 SG_ S2P_Cfg12_SW_Ver_Byte6_52 : 40|8@1+ (1,0) [0|255] ""  PC
 SG_ S2P_Cfg12_SW_Ver_Byte7_52 : 48|8@1+ (1,0) [0|255] ""  PC
 SG_ S2P_Cfg12_SW_Ver_Byte8_52 : 56|8@1+ (1,0) [0|255] ""  PC

BO_ 2418601589 S2P_Cfg12__53: 8 SBMU
 SG_ S2P_Cfg12_SW_Ver_Byte1_53 : 0|8@1+ (1,0) [0|255] ""  PC
 SG_ S2P_Cfg12_SW_Ver_Byte2_53 : 8|8@1+ (1,0) [0|255] ""  PC
 SG_ S2P_Cfg12_SW_Ver_Byte3_53 : 16|8@1+ (1,0) [0|255] ""  PC
 SG_ S2P_Cfg12_SW_Ver_Byte4_53 : 24|8@1+ (1,0) [0|255] ""  PC
 SG_ S2P_Cfg12_SW_Ver_Byte5_53 : 32|8@1+ (1,0) [0|255] ""  PC
 SG_ S2P_Cfg12_SW_Ver_Byte6_53 : 40|8@1+ (1,0) [0|255] ""  PC
 SG_ S2P_Cfg12_SW_Ver_Byte7_53 : 48|8@1+ (1,0) [0|255] ""  PC
 SG_ S2P_Cfg12_SW_Ver_Byte8_53 : 56|8@1+ (1,0) [0|255] ""  PC

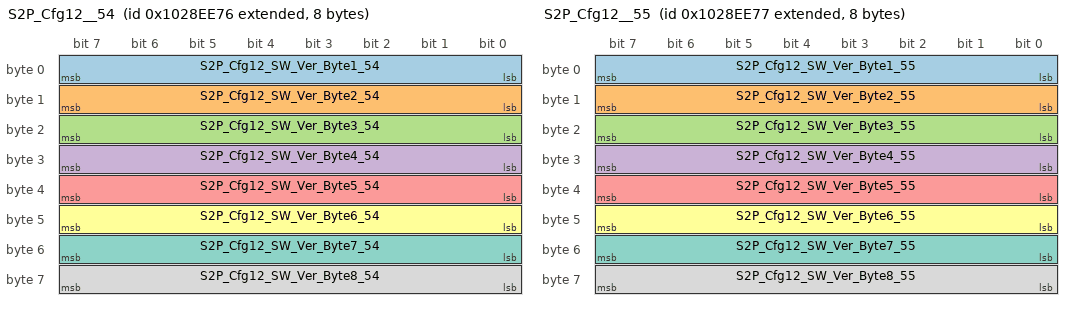
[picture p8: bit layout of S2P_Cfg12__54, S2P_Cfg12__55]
BO_ 2418601590 S2P_Cfg12__54: 8 SBMU
 SG_ S2P_Cfg12_SW_Ver_Byte1_54 : 0|8@1+ (1,0) [0|255] ""  PC
 SG_ S2P_Cfg12_SW_Ver_Byte2_54 : 8|8@1+ (1,0) [0|255] ""  PC
 SG_ S2P_Cfg12_SW_Ver_Byte3_54 : 16|8@1+ (1,0) [0|255] ""  PC
 SG_ S2P_Cfg12_SW_Ver_Byte4_54 : 24|8@1+ (1,0) [0|255] ""  PC
 SG_ S2P_Cfg12_SW_Ver_Byte5_54 : 32|8@1+ (1,0) [0|255] ""  PC
 SG_ S2P_Cfg12_SW_Ver_Byte6_54 : 40|8@1+ (1,0) [0|255] ""  PC
 SG_ S2P_Cfg12_SW_Ver_Byte7_54 : 48|8@1+ (1,0) [0|255] ""  PC
 SG_ S2P_Cfg12_SW_Ver_Byte8_54 : 56|8@1+ (1,0) [0|255] ""  PC

BO_ 2418601591 S2P_Cfg12__55: 8 SBMU
 SG_ S2P_Cfg12_SW_Ver_Byte1_55 : 0|8@1+ (1,0) [0|255] ""  PC
 SG_ S2P_Cfg12_SW_Ver_Byte2_55 : 8|8@1+ (1,0) [0|255] ""  PC
 SG_ S2P_Cfg12_SW_Ver_Byte3_55 : 16|8@1+ (1,0) [0|255] ""  PC
 SG_ S2P_Cfg12_SW_Ver_Byte4_55 : 24|8@1+ (1,0) [0|255] ""  PC
 SG_ S2P_Cfg12_SW_Ver_Byte5_55 : 32|8@1+ (1,0) [0|255] ""  PC
 SG_ S2P_Cfg12_SW_Ver_Byte6_55 : 40|8@1+ (1,0) [0|255] ""  PC
 SG_ S2P_Cfg12_SW_Ver_Byte7_55 : 48|8@1+ (1,0) [0|255] ""  PC
 SG_ S2P_Cfg12_SW_Ver_Byte8_55 : 56|8@1+ (1,0) [0|255] ""  PC

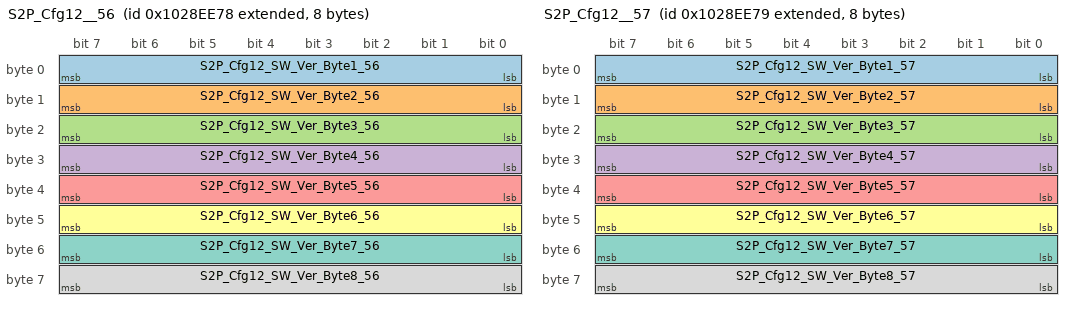
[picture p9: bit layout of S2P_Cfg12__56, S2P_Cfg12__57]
BO_ 2418601592 S2P_Cfg12__56: 8 SBMU
 SG_ S2P_Cfg12_SW_Ver_Byte1_56 : 0|8@1+ (1,0) [0|255] ""  PC
 SG_ S2P_Cfg12_SW_Ver_Byte2_56 : 8|8@1+ (1,0) [0|255] ""  PC
 SG_ S2P_Cfg12_SW_Ver_Byte3_56 : 16|8@1+ (1,0) [0|255] ""  PC
 SG_ S2P_Cfg12_SW_Ver_Byte4_56 : 24|8@1+ (1,0) [0|255] ""  PC
 SG_ S2P_Cfg12_SW_Ver_Byte5_56 : 32|8@1+ (1,0) [0|255] ""  PC
 SG_ S2P_Cfg12_SW_Ver_Byte6_56 : 40|8@1+ (1,0) [0|255] ""  PC
 SG_ S2P_Cfg12_SW_Ver_Byte7_56 : 48|8@1+ (1,0) [0|255] ""  PC
 SG_ S2P_Cfg12_SW_Ver_Byte8_56 : 56|8@1+ (1,0) [0|255] ""  PC

BO_ 2418601593 S2P_Cfg12__57: 8 SBMU
 SG_ S2P_Cfg12_SW_Ver_Byte1_57 : 0|8@1+ (1,0) [0|255] ""  PC
 SG_ S2P_Cfg12_SW_Ver_Byte2_57 : 8|8@1+ (1,0) [0|255] ""  PC
 SG_ S2P_Cfg12_SW_Ver_Byte3_57 : 16|8@1+ (1,0) [0|255] ""  PC
 SG_ S2P_Cfg12_SW_Ver_Byte4_57 : 24|8@1+ (1,0) [0|255] ""  PC
 SG_ S2P_Cfg12_SW_Ver_Byte5_57 : 32|8@1+ (1,0) [0|255] ""  PC
 SG_ S2P_Cfg12_SW_Ver_Byte6_57 : 40|8@1+ (1,0) [0|255] ""  PC
 SG_ S2P_Cfg12_SW_Ver_Byte7_57 : 48|8@1+ (1,0) [0|255] ""  PC
 SG_ S2P_Cfg12_SW_Ver_Byte8_57 : 56|8@1+ (1,0) [0|255] ""  PC

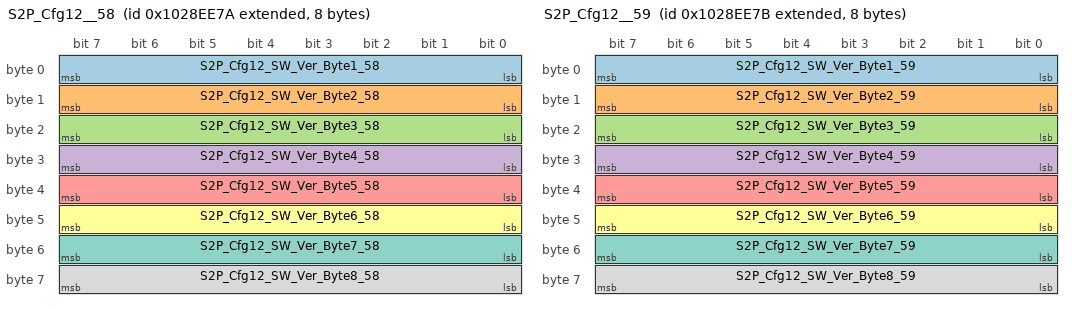
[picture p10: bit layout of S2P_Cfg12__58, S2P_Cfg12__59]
BO_ 2418601594 S2P_Cfg12__58: 8 SBMU
 SG_ S2P_Cfg12_SW_Ver_Byte1_58 : 0|8@1+ (1,0) [0|255] ""  PC
 SG_ S2P_Cfg12_SW_Ver_Byte2_58 : 8|8@1+ (1,0) [0|255] ""  PC
 SG_ S2P_Cfg12_SW_Ver_Byte3_58 : 16|8@1+ (1,0) [0|255] ""  PC
 SG_ S2P_Cfg12_SW_Ver_Byte4_58 : 24|8@1+ (1,0) [0|255] ""  PC
 SG_ S2P_Cfg12_SW_Ver_Byte5_58 : 32|8@1+ (1,0) [0|255] ""  PC
 SG_ S2P_Cfg12_SW_Ver_Byte6_58 : 40|8@1+ (1,0) [0|255] ""  PC
 SG_ S2P_Cfg12_SW_Ver_Byte7_58 : 48|8@1+ (1,0) [0|255] ""  PC
 SG_ S2P_Cfg12_SW_Ver_Byte8_58 : 56|8@1+ (1,0) [0|255] ""  PC

BO_ 2418601595 S2P_Cfg12__59: 8 SBMU
 SG_ S2P_Cfg12_SW_Ver_Byte1_59 : 0|8@1+ (1,0) [0|255] ""  PC
 SG_ S2P_Cfg12_SW_Ver_Byte2_59 : 8|8@1+ (1,0) [0|255] ""  PC
 SG_ S2P_Cfg12_SW_Ver_Byte3_59 : 16|8@1+ (1,0) [0|255] ""  PC
 SG_ S2P_Cfg12_SW_Ver_Byte4_59 : 24|8@1+ (1,0) [0|255] ""  PC
 SG_ S2P_Cfg12_SW_Ver_Byte5_59 : 32|8@1+ (1,0) [0|255] ""  PC
 SG_ S2P_Cfg12_SW_Ver_Byte6_59 : 40|8@1+ (1,0) [0|255] ""  PC
 SG_ S2P_Cfg12_SW_Ver_Byte7_59 : 48|8@1+ (1,0) [0|255] ""  PC
 SG_ S2P_Cfg12_SW_Ver_Byte8_59 : 56|8@1+ (1,0) [0|255] ""  PC

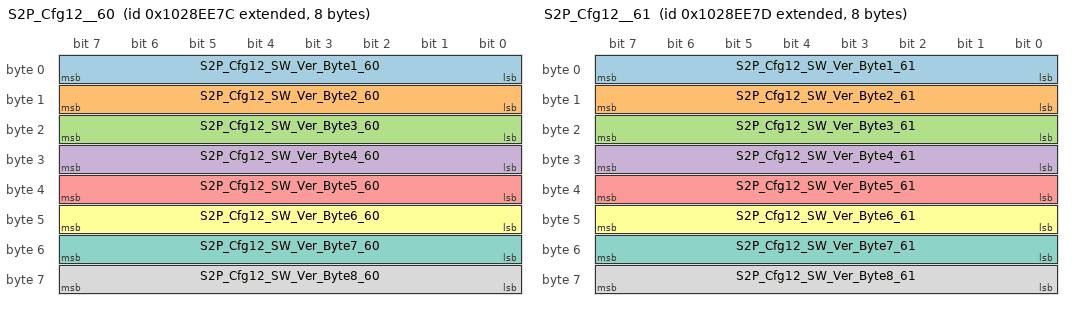
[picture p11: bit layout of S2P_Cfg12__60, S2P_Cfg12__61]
BO_ 2418601596 S2P_Cfg12__60: 8 SBMU
 SG_ S2P_Cfg12_SW_Ver_Byte1_60 : 0|8@1+ (1,0) [0|255] ""  PC
 SG_ S2P_Cfg12_SW_Ver_Byte2_60 : 8|8@1+ (1,0) [0|255] ""  PC
 SG_ S2P_Cfg12_SW_Ver_Byte3_60 : 16|8@1+ (1,0) [0|255] ""  PC
 SG_ S2P_Cfg12_SW_Ver_Byte4_60 : 24|8@1+ (1,0) [0|255] ""  PC
 SG_ S2P_Cfg12_SW_Ver_Byte5_60 : 32|8@1+ (1,0) [0|255] ""  PC
 SG_ S2P_Cfg12_SW_Ver_Byte6_60 : 40|8@1+ (1,0) [0|255] ""  PC
 SG_ S2P_Cfg12_SW_Ver_Byte7_60 : 48|8@1+ (1,0) [0|255] ""  PC
 SG_ S2P_Cfg12_SW_Ver_Byte8_60 : 56|8@1+ (1,0) [0|255] ""  PC

BO_ 2418601597 S2P_Cfg12__61: 8 SBMU
 SG_ S2P_Cfg12_SW_Ver_Byte1_61 : 0|8@1+ (1,0) [0|255] ""  PC
 SG_ S2P_Cfg12_SW_Ver_Byte2_61 : 8|8@1+ (1,0) [0|255] ""  PC
 SG_ S2P_Cfg12_SW_Ver_Byte3_61 : 16|8@1+ (1,0) [0|255] ""  PC
 SG_ S2P_Cfg12_SW_Ver_Byte4_61 : 24|8@1+ (1,0) [0|255] ""  PC
 SG_ S2P_Cfg12_SW_Ver_Byte5_61 : 32|8@1+ (1,0) [0|255] ""  PC
 SG_ S2P_Cfg12_SW_Ver_Byte6_61 : 40|8@1+ (1,0) [0|255] ""  PC
 SG_ S2P_Cfg12_SW_Ver_Byte7_61 : 48|8@1+ (1,0) [0|255] ""  PC
 SG_ S2P_Cfg12_SW_Ver_Byte8_61 : 56|8@1+ (1,0) [0|255] ""  PC

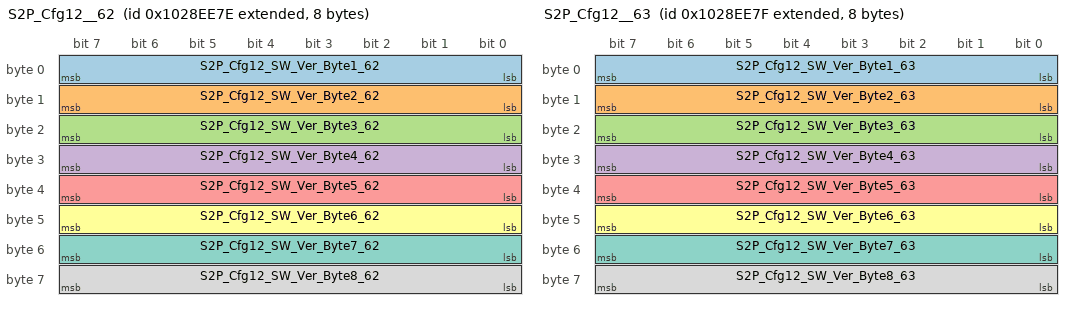
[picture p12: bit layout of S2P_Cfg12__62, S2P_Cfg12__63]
BO_ 2418601598 S2P_Cfg12__62: 8 SBMU
 SG_ S2P_Cfg12_SW_Ver_Byte1_62 : 0|8@1+ (1,0) [0|255] ""  PC
 SG_ S2P_Cfg12_SW_Ver_Byte2_62 : 8|8@1+ (1,0) [0|255] ""  PC
 SG_ S2P_Cfg12_SW_Ver_Byte3_62 : 16|8@1+ (1,0) [0|255] ""  PC
 SG_ S2P_Cfg12_SW_Ver_Byte4_62 : 24|8@1+ (1,0) [0|255] ""  PC
 SG_ S2P_Cfg12_SW_Ver_Byte5_62 : 32|8@1+ (1,0) [0|255] ""  PC
 SG_ S2P_Cfg12_SW_Ver_Byte6_62 : 40|8@1+ (1,0) [0|255] ""  PC
 SG_ S2P_Cfg12_SW_Ver_Byte7_62 : 48|8@1+ (1,0) [0|255] ""  PC
 SG_ S2P_Cfg12_SW_Ver_Byte8_62 : 56|8@1+ (1,0) [0|255] ""  PC

BO_ 2418601599 S2P_Cfg12__63: 8 SBMU
 SG_ S2P_Cfg12_SW_Ver_Byte1_63 : 0|8@1+ (1,0) [0|255] ""  PC
 SG_ S2P_Cfg12_SW_Ver_Byte2_63 : 8|8@1+ (1,0) [0|255] ""  PC
 SG_ S2P_Cfg12_SW_Ver_Byte3_63 : 16|8@1+ (1,0) [0|255] ""  PC
 SG_ S2P_Cfg12_SW_Ver_Byte4_63 : 24|8@1+ (1,0) [0|255] ""  PC
 SG_ S2P_Cfg12_SW_Ver_Byte5_63 : 32|8@1+ (1,0) [0|255] ""  PC
 SG_ S2P_Cfg12_SW_Ver_Byte6_63 : 40|8@1+ (1,0) [0|255] ""  PC
 SG_ S2P_Cfg12_SW_Ver_Byte7_63 : 48|8@1+ (1,0) [0|255] ""  PC
 SG_ S2P_Cfg12_SW_Ver_Byte8_63 : 56|8@1+ (1,0) [0|255] ""  PC

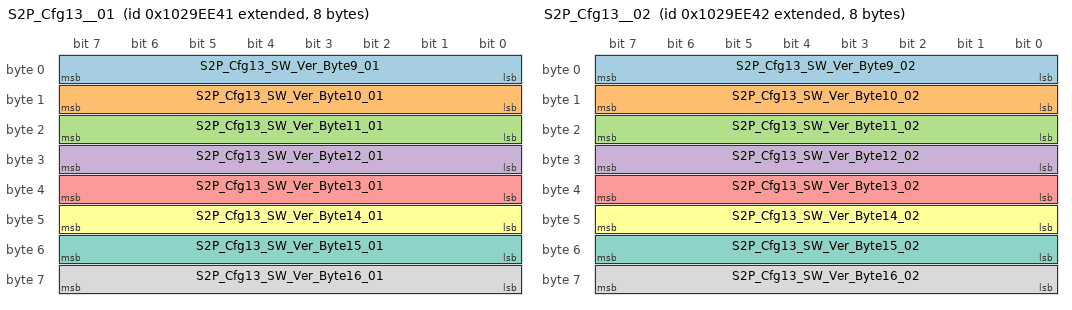
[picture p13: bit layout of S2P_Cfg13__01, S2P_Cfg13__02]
BO_ 2418667073 S2P_Cfg13__01: 8 SBMU
 SG_ S2P_Cfg13_SW_Ver_Byte9_01 : 0|8@1+ (1,0) [0|255] ""  PC
 SG_ S2P_Cfg13_SW_Ver_Byte10_01 : 8|8@1+ (1,0) [0|255] ""  PC
 SG_ S2P_Cfg13_SW_Ver_Byte11_01 : 16|8@1+ (1,0) [0|255] ""  PC
 SG_ S2P_Cfg13_SW_Ver_Byte12_01 : 24|8@1+ (1,0) [0|255] ""  PC
 SG_ S2P_Cfg13_SW_Ver_Byte13_01 : 32|8@1+ (1,0) [0|255] ""  PC
 SG_ S2P_Cfg13_SW_Ver_Byte14_01 : 40|8@1+ (1,0) [0|255] ""  PC
 SG_ S2P_Cfg13_SW_Ver_Byte15_01 : 48|8@1+ (1,0) [0|255] ""  PC
 SG_ S2P_Cfg13_SW_Ver_Byte16_01 : 56|8@1+ (1,0) [0|255] ""  PC

BO_ 2418667074 S2P_Cfg13__02: 8 SBMU
 SG_ S2P_Cfg13_SW_Ver_Byte9_02 : 0|8@1+ (1,0) [0|255] ""  PC
 SG_ S2P_Cfg13_SW_Ver_Byte10_02 : 8|8@1+ (1,0) [0|255] ""  PC
 SG_ S2P_Cfg13_SW_Ver_Byte11_02 : 16|8@1+ (1,0) [0|255] ""  PC
 SG_ S2P_Cfg13_SW_Ver_Byte12_02 : 24|8@1+ (1,0) [0|255] ""  PC
 SG_ S2P_Cfg13_SW_Ver_Byte13_02 : 32|8@1+ (1,0) [0|255] ""  PC
 SG_ S2P_Cfg13_SW_Ver_Byte14_02 : 40|8@1+ (1,0) [0|255] ""  PC
 SG_ S2P_Cfg13_SW_Ver_Byte15_02 : 48|8@1+ (1,0) [0|255] ""  PC
 SG_ S2P_Cfg13_SW_Ver_Byte16_02 : 56|8@1+ (1,0) [0|255] ""  PC

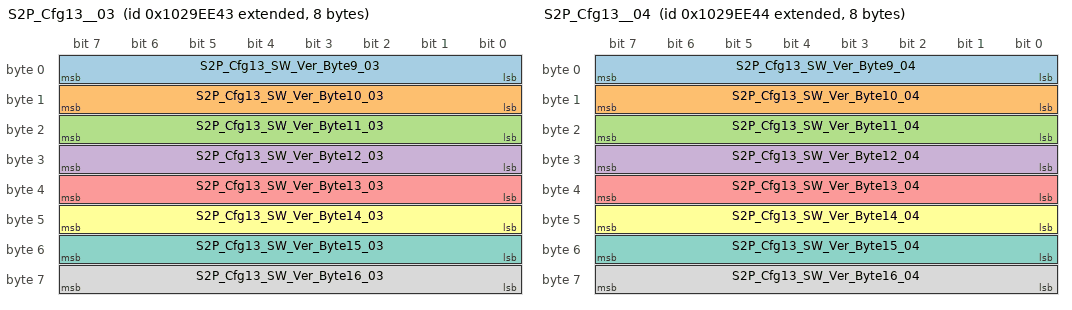
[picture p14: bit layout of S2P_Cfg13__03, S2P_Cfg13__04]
BO_ 2418667075 S2P_Cfg13__03: 8 SBMU
 SG_ S2P_Cfg13_SW_Ver_Byte9_03 : 0|8@1+ (1,0) [0|255] ""  PC
 SG_ S2P_Cfg13_SW_Ver_Byte10_03 : 8|8@1+ (1,0) [0|255] ""  PC
 SG_ S2P_Cfg13_SW_Ver_Byte11_03 : 16|8@1+ (1,0) [0|255] ""  PC
 SG_ S2P_Cfg13_SW_Ver_Byte12_03 : 24|8@1+ (1,0) [0|255] ""  PC
 SG_ S2P_Cfg13_SW_Ver_Byte13_03 : 32|8@1+ (1,0) [0|255] ""  PC
 SG_ S2P_Cfg13_SW_Ver_Byte14_03 : 40|8@1+ (1,0) [0|255] ""  PC
 SG_ S2P_Cfg13_SW_Ver_Byte15_03 : 48|8@1+ (1,0) [0|255] ""  PC
 SG_ S2P_Cfg13_SW_Ver_Byte16_03 : 56|8@1+ (1,0) [0|255] ""  PC

BO_ 2418667076 S2P_Cfg13__04: 8 SBMU
 SG_ S2P_Cfg13_SW_Ver_Byte9_04 : 0|8@1+ (1,0) [0|255] ""  PC
 SG_ S2P_Cfg13_SW_Ver_Byte10_04 : 8|8@1+ (1,0) [0|255] ""  PC
 SG_ S2P_Cfg13_SW_Ver_Byte11_04 : 16|8@1+ (1,0) [0|255] ""  PC
 SG_ S2P_Cfg13_SW_Ver_Byte12_04 : 24|8@1+ (1,0) [0|255] ""  PC
 SG_ S2P_Cfg13_SW_Ver_Byte13_04 : 32|8@1+ (1,0) [0|255] ""  PC
 SG_ S2P_Cfg13_SW_Ver_Byte14_04 : 40|8@1+ (1,0) [0|255] ""  PC
 SG_ S2P_Cfg13_SW_Ver_Byte15_04 : 48|8@1+ (1,0) [0|255] ""  PC
 SG_ S2P_Cfg13_SW_Ver_Byte16_04 : 56|8@1+ (1,0) [0|255] ""  PC

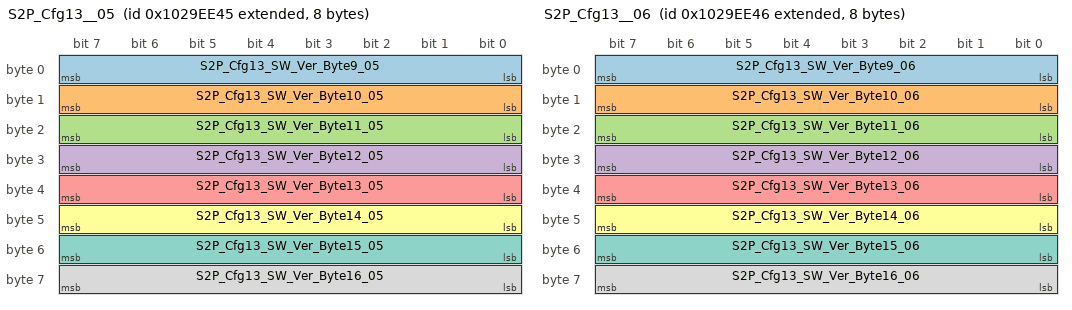
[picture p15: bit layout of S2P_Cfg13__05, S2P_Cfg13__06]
BO_ 2418667077 S2P_Cfg13__05: 8 SBMU
 SG_ S2P_Cfg13_SW_Ver_Byte9_05 : 0|8@1+ (1,0) [0|255] ""  PC
 SG_ S2P_Cfg13_SW_Ver_Byte10_05 : 8|8@1+ (1,0) [0|255] ""  PC
 SG_ S2P_Cfg13_SW_Ver_Byte11_05 : 16|8@1+ (1,0) [0|255] ""  PC
 SG_ S2P_Cfg13_SW_Ver_Byte12_05 : 24|8@1+ (1,0) [0|255] ""  PC
 SG_ S2P_Cfg13_SW_Ver_Byte13_05 : 32|8@1+ (1,0) [0|255] ""  PC
 SG_ S2P_Cfg13_SW_Ver_Byte14_05 : 40|8@1+ (1,0) [0|255] ""  PC
 SG_ S2P_Cfg13_SW_Ver_Byte15_05 : 48|8@1+ (1,0) [0|255] ""  PC
 SG_ S2P_Cfg13_SW_Ver_Byte16_05 : 56|8@1+ (1,0) [0|255] ""  PC

BO_ 2418667078 S2P_Cfg13__06: 8 SBMU
 SG_ S2P_Cfg13_SW_Ver_Byte9_06 : 0|8@1+ (1,0) [0|255] ""  PC
 SG_ S2P_Cfg13_SW_Ver_Byte10_06 : 8|8@1+ (1,0) [0|255] ""  PC
 SG_ S2P_Cfg13_SW_Ver_Byte11_06 : 16|8@1+ (1,0) [0|255] ""  PC
 SG_ S2P_Cfg13_SW_Ver_Byte12_06 : 24|8@1+ (1,0) [0|255] ""  PC
 SG_ S2P_Cfg13_SW_Ver_Byte13_06 : 32|8@1+ (1,0) [0|255] ""  PC
 SG_ S2P_Cfg13_SW_Ver_Byte14_06 : 40|8@1+ (1,0) [0|255] ""  PC
 SG_ S2P_Cfg13_SW_Ver_Byte15_06 : 48|8@1+ (1,0) [0|255] ""  PC
 SG_ S2P_Cfg13_SW_Ver_Byte16_06 : 56|8@1+ (1,0) [0|255] ""  PC

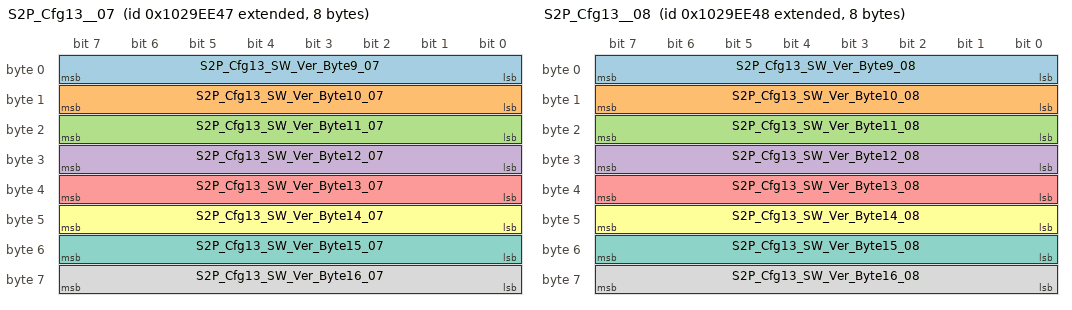
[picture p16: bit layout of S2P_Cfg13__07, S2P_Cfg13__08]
BO_ 2418667079 S2P_Cfg13__07: 8 SBMU
 SG_ S2P_Cfg13_SW_Ver_Byte9_07 : 0|8@1+ (1,0) [0|255] ""  PC
 SG_ S2P_Cfg13_SW_Ver_Byte10_07 : 8|8@1+ (1,0) [0|255] ""  PC
 SG_ S2P_Cfg13_SW_Ver_Byte11_07 : 16|8@1+ (1,0) [0|255] ""  PC
 SG_ S2P_Cfg13_SW_Ver_Byte12_07 : 24|8@1+ (1,0) [0|255] ""  PC
 SG_ S2P_Cfg13_SW_Ver_Byte13_07 : 32|8@1+ (1,0) [0|255] ""  PC
 SG_ S2P_Cfg13_SW_Ver_Byte14_07 : 40|8@1+ (1,0) [0|255] ""  PC
 SG_ S2P_Cfg13_SW_Ver_Byte15_07 : 48|8@1+ (1,0) [0|255] ""  PC
 SG_ S2P_Cfg13_SW_Ver_Byte16_07 : 56|8@1+ (1,0) [0|255] ""  PC

BO_ 2418667080 S2P_Cfg13__08: 8 SBMU
 SG_ S2P_Cfg13_SW_Ver_Byte9_08 : 0|8@1+ (1,0) [0|255] ""  PC
 SG_ S2P_Cfg13_SW_Ver_Byte10_08 : 8|8@1+ (1,0) [0|255] ""  PC
 SG_ S2P_Cfg13_SW_Ver_Byte11_08 : 16|8@1+ (1,0) [0|255] ""  PC
 SG_ S2P_Cfg13_SW_Ver_Byte12_08 : 24|8@1+ (1,0) [0|255] ""  PC
 SG_ S2P_Cfg13_SW_Ver_Byte13_08 : 32|8@1+ (1,0) [0|255] ""  PC
 SG_ S2P_Cfg13_SW_Ver_Byte14_08 : 40|8@1+ (1,0) [0|255] ""  PC
 SG_ S2P_Cfg13_SW_Ver_Byte15_08 : 48|8@1+ (1,0) [0|255] ""  PC
 SG_ S2P_Cfg13_SW_Ver_Byte16_08 : 56|8@1+ (1,0) [0|255] ""  PC

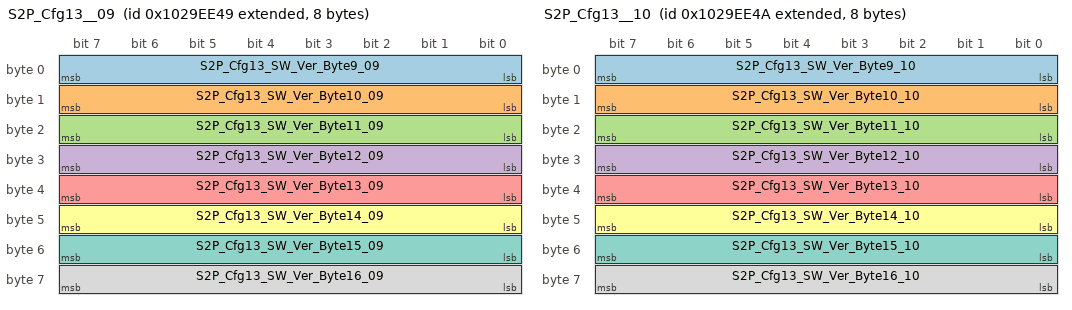
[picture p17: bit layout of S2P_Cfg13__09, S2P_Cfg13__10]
BO_ 2418667081 S2P_Cfg13__09: 8 SBMU
 SG_ S2P_Cfg13_SW_Ver_Byte9_09 : 0|8@1+ (1,0) [0|255] ""  PC
 SG_ S2P_Cfg13_SW_Ver_Byte10_09 : 8|8@1+ (1,0) [0|255] ""  PC
 SG_ S2P_Cfg13_SW_Ver_Byte11_09 : 16|8@1+ (1,0) [0|255] ""  PC
 SG_ S2P_Cfg13_SW_Ver_Byte12_09 : 24|8@1+ (1,0) [0|255] ""  PC
 SG_ S2P_Cfg13_SW_Ver_Byte13_09 : 32|8@1+ (1,0) [0|255] ""  PC
 SG_ S2P_Cfg13_SW_Ver_Byte14_09 : 40|8@1+ (1,0) [0|255] ""  PC
 SG_ S2P_Cfg13_SW_Ver_Byte15_09 : 48|8@1+ (1,0) [0|255] ""  PC
 SG_ S2P_Cfg13_SW_Ver_Byte16_09 : 56|8@1+ (1,0) [0|255] ""  PC

BO_ 2418667082 S2P_Cfg13__10: 8 SBMU
 SG_ S2P_Cfg13_SW_Ver_Byte9_10 : 0|8@1+ (1,0) [0|255] ""  PC
 SG_ S2P_Cfg13_SW_Ver_Byte10_10 : 8|8@1+ (1,0) [0|255] ""  PC
 SG_ S2P_Cfg13_SW_Ver_Byte11_10 : 16|8@1+ (1,0) [0|255] ""  PC
 SG_ S2P_Cfg13_SW_Ver_Byte12_10 : 24|8@1+ (1,0) [0|255] ""  PC
 SG_ S2P_Cfg13_SW_Ver_Byte13_10 : 32|8@1+ (1,0) [0|255] ""  PC
 SG_ S2P_Cfg13_SW_Ver_Byte14_10 : 40|8@1+ (1,0) [0|255] ""  PC
 SG_ S2P_Cfg13_SW_Ver_Byte15_10 : 48|8@1+ (1,0) [0|255] ""  PC
 SG_ S2P_Cfg13_SW_Ver_Byte16_10 : 56|8@1+ (1,0) [0|255] ""  PC

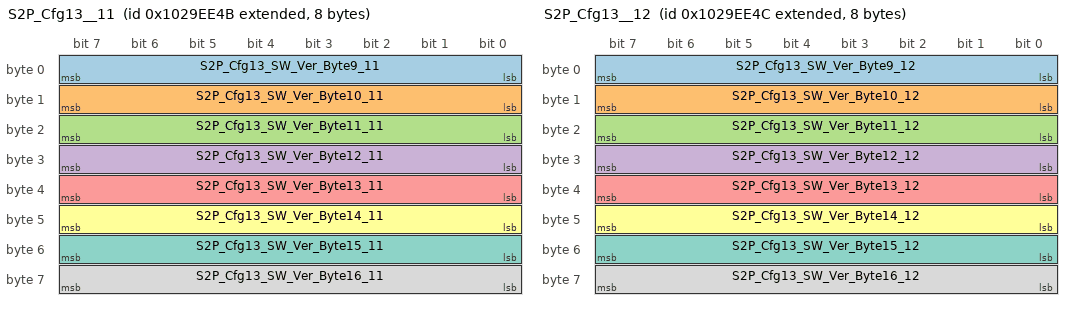
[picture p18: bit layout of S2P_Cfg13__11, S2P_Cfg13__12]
BO_ 2418667083 S2P_Cfg13__11: 8 SBMU
 SG_ S2P_Cfg13_SW_Ver_Byte9_11 : 0|8@1+ (1,0) [0|255] ""  PC
 SG_ S2P_Cfg13_SW_Ver_Byte10_11 : 8|8@1+ (1,0) [0|255] ""  PC
 SG_ S2P_Cfg13_SW_Ver_Byte11_11 : 16|8@1+ (1,0) [0|255] ""  PC
 SG_ S2P_Cfg13_SW_Ver_Byte12_11 : 24|8@1+ (1,0) [0|255] ""  PC
 SG_ S2P_Cfg13_SW_Ver_Byte13_11 : 32|8@1+ (1,0) [0|255] ""  PC
 SG_ S2P_Cfg13_SW_Ver_Byte14_11 : 40|8@1+ (1,0) [0|255] ""  PC
 SG_ S2P_Cfg13_SW_Ver_Byte15_11 : 48|8@1+ (1,0) [0|255] ""  PC
 SG_ S2P_Cfg13_SW_Ver_Byte16_11 : 56|8@1+ (1,0) [0|255] ""  PC

BO_ 2418667084 S2P_Cfg13__12: 8 SBMU
 SG_ S2P_Cfg13_SW_Ver_Byte9_12 : 0|8@1+ (1,0) [0|255] ""  PC
 SG_ S2P_Cfg13_SW_Ver_Byte10_12 : 8|8@1+ (1,0) [0|255] ""  PC
 SG_ S2P_Cfg13_SW_Ver_Byte11_12 : 16|8@1+ (1,0) [0|255] ""  PC
 SG_ S2P_Cfg13_SW_Ver_Byte12_12 : 24|8@1+ (1,0) [0|255] ""  PC
 SG_ S2P_Cfg13_SW_Ver_Byte13_12 : 32|8@1+ (1,0) [0|255] ""  PC
 SG_ S2P_Cfg13_SW_Ver_Byte14_12 : 40|8@1+ (1,0) [0|255] ""  PC
 SG_ S2P_Cfg13_SW_Ver_Byte15_12 : 48|8@1+ (1,0) [0|255] ""  PC
 SG_ S2P_Cfg13_SW_Ver_Byte16_12 : 56|8@1+ (1,0) [0|255] ""  PC

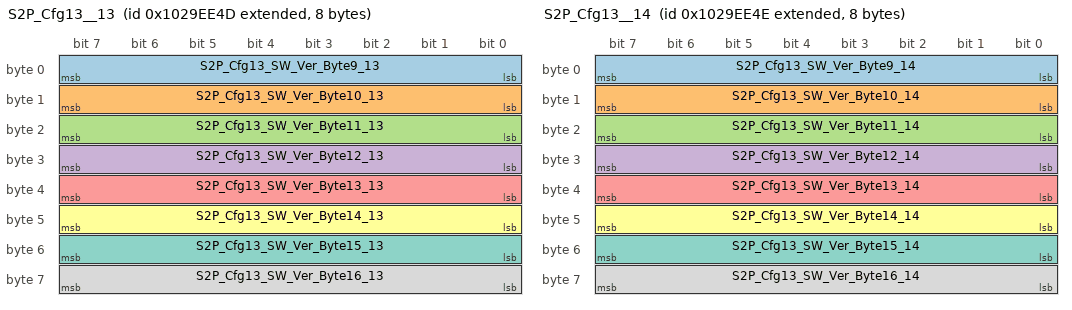
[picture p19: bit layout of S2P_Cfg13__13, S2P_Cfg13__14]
BO_ 2418667085 S2P_Cfg13__13: 8 SBMU
 SG_ S2P_Cfg13_SW_Ver_Byte9_13 : 0|8@1+ (1,0) [0|255] ""  PC
 SG_ S2P_Cfg13_SW_Ver_Byte10_13 : 8|8@1+ (1,0) [0|255] ""  PC
 SG_ S2P_Cfg13_SW_Ver_Byte11_13 : 16|8@1+ (1,0) [0|255] ""  PC
 SG_ S2P_Cfg13_SW_Ver_Byte12_13 : 24|8@1+ (1,0) [0|255] ""  PC
 SG_ S2P_Cfg13_SW_Ver_Byte13_13 : 32|8@1+ (1,0) [0|255] ""  PC
 SG_ S2P_Cfg13_SW_Ver_Byte14_13 : 40|8@1+ (1,0) [0|255] ""  PC
 SG_ S2P_Cfg13_SW_Ver_Byte15_13 : 48|8@1+ (1,0) [0|255] ""  PC
 SG_ S2P_Cfg13_SW_Ver_Byte16_13 : 56|8@1+ (1,0) [0|255] ""  PC

BO_ 2418667086 S2P_Cfg13__14: 8 SBMU
 SG_ S2P_Cfg13_SW_Ver_Byte9_14 : 0|8@1+ (1,0) [0|255] ""  PC
 SG_ S2P_Cfg13_SW_Ver_Byte10_14 : 8|8@1+ (1,0) [0|255] ""  PC
 SG_ S2P_Cfg13_SW_Ver_Byte11_14 : 16|8@1+ (1,0) [0|255] ""  PC
 SG_ S2P_Cfg13_SW_Ver_Byte12_14 : 24|8@1+ (1,0) [0|255] ""  PC
 SG_ S2P_Cfg13_SW_Ver_Byte13_14 : 32|8@1+ (1,0) [0|255] ""  PC
 SG_ S2P_Cfg13_SW_Ver_Byte14_14 : 40|8@1+ (1,0) [0|255] ""  PC
 SG_ S2P_Cfg13_SW_Ver_Byte15_14 : 48|8@1+ (1,0) [0|255] ""  PC
 SG_ S2P_Cfg13_SW_Ver_Byte16_14 : 56|8@1+ (1,0) [0|255] ""  PC

BO_ 2418667087 S2P_Cfg13__15: 8 SBMU
 SG_ S2P_Cfg13_SW_Ver_Byte9_15 : 0|8@1+ (1,0) [0|255] ""  PC
 SG_ S2P_Cfg13_SW_Ver_Byte10_15 : 8|8@1+ (1,0) [0|255] ""  PC
 SG_ S2P_Cfg13_SW_Ver_Byte11_15 : 16|8@1+ (1,0) [0|255] ""  PC
 SG_ S2P_Cfg13_SW_Ver_Byte12_15 : 24|8@1+ (1,0) [0|255] ""  PC
 SG_ S2P_Cfg13_SW_Ver_Byte13_15 : 32|8@1+ (1,0) [0|255] ""  PC
 SG_ S2P_Cfg13_SW_Ver_Byte14_15 : 40|8@1+ (1,0) [0|255] ""  PC
 SG_ S2P_Cfg13_SW_Ver_Byte15_15 : 48|8@1+ (1,0) [0|255] ""  PC
 SG_ S2P_Cfg13_SW_Ver_Byte16_15 : 56|8@1+ (1,0) [0|255] ""  PC

BO_ 2418667088 S2P_Cfg13__16: 8 SBMU
 SG_ S2P_Cfg13_SW_Ver_Byte9_16 : 0|8@1+ (1,0) [0|255] ""  PC
 SG_ S2P_Cfg13_SW_Ver_Byte10_16 : 8|8@1+ (1,0) [0|255] ""  PC
 SG_ S2P_Cfg13_SW_Ver_Byte11_16 : 16|8@1+ (1,0) [0|255] ""  PC
 SG_ S2P_Cfg13_SW_Ver_Byte12_16 : 24|8@1+ (1,0) [0|255] ""  PC
 SG_ S2P_Cfg13_SW_Ver_Byte13_16 : 32|8@1+ (1,0) [0|255] ""  PC
 SG_ S2P_Cfg13_SW_Ver_Byte14_16 : 40|8@1+ (1,0) [0|255] ""  PC
 SG_ S2P_Cfg13_SW_Ver_Byte15_16 : 48|8@1+ (1,0) [0|255] ""  PC
 SG_ S2P_Cfg13_SW_Ver_Byte16_16 : 56|8@1+ (1,0) [0|255] ""  PC

BO_ 2418667089 S2P_Cfg13__17: 8 SBMU
 SG_ S2P_Cfg13_SW_Ver_Byte9_17 : 0|8@1+ (1,0) [0|255] ""  PC
 SG_ S2P_Cfg13_SW_Ver_Byte10_17 : 8|8@1+ (1,0) [0|255] ""  PC
 SG_ S2P_Cfg13_SW_Ver_Byte11_17 : 16|8@1+ (1,0) [0|255] ""  PC
 SG_ S2P_Cfg13_SW_Ver_Byte12_17 : 24|8@1+ (1,0) [0|255] ""  PC
 SG_ S2P_Cfg13_SW_Ver_Byte13_17 : 32|8@1+ (1,0) [0|255] ""  PC
 SG_ S2P_Cfg13_SW_Ver_Byte14_17 : 40|8@1+ (1,0) [0|255] ""  PC
 SG_ S2P_Cfg13_SW_Ver_Byte15_17 : 48|8@1+ (1,0) [0|255] ""  PC
 SG_ S2P_Cfg13_SW_Ver_Byte16_17 : 56|8@1+ (1,0) [0|255] ""  PC

BO_ 2418667090 S2P_Cfg13__18: 8 SBMU
 SG_ S2P_Cfg13_SW_Ver_Byte9_18 : 0|8@1+ (1,0) [0|255] ""  PC
 SG_ S2P_Cfg13_SW_Ver_Byte10_18 : 8|8@1+ (1,0) [0|255] ""  PC
 SG_ S2P_Cfg13_SW_Ver_Byte11_18 : 16|8@1+ (1,0) [0|255] ""  PC
 SG_ S2P_Cfg13_SW_Ver_Byte12_18 : 24|8@1+ (1,0) [0|255] ""  PC
 SG_ S2P_Cfg13_SW_Ver_Byte13_18 : 32|8@1+ (1,0) [0|255] ""  PC
 SG_ S2P_Cfg13_SW_Ver_Byte14_18 : 40|8@1+ (1,0) [0|255] ""  PC
 SG_ S2P_Cfg13_SW_Ver_Byte15_18 : 48|8@1+ (1,0) [0|255] ""  PC
 SG_ S2P_Cfg13_SW_Ver_Byte16_18 : 56|8@1+ (1,0) [0|255] ""  PC

BO_ 2418667091 S2P_Cfg13__19: 8 SBMU
 SG_ S2P_Cfg13_SW_Ver_Byte9_19 : 0|8@1+ (1,0) [0|255] ""  PC
 SG_ S2P_Cfg13_SW_Ver_Byte10_19 : 8|8@1+ (1,0) [0|255] ""  PC
 SG_ S2P_Cfg13_SW_Ver_Byte11_19 : 16|8@1+ (1,0) [0|255] ""  PC
 SG_ S2P_Cfg13_SW_Ver_Byte12_19 : 24|8@1+ (1,0) [0|255] ""  PC
 SG_ S2P_Cfg13_SW_Ver_Byte13_19 : 32|8@1+ (1,0) [0|255] ""  PC
 SG_ S2P_Cfg13_SW_Ver_Byte14_19 : 40|8@1+ (1,0) [0|255] ""  PC
 SG_ S2P_Cfg13_SW_Ver_Byte15_19 : 48|8@1+ (1,0) [0|255] ""  PC
 SG_ S2P_Cfg13_SW_Ver_Byte16_19 : 56|8@1+ (1,0) [0|255] ""  PC

BO_ 2418667092 S2P_Cfg13__20: 8 SBMU
 SG_ S2P_Cfg13_SW_Ver_Byte9_20 : 0|8@1+ (1,0) [0|255] ""  PC
 SG_ S2P_Cfg13_SW_Ver_Byte10_20 : 8|8@1+ (1,0) [0|255] ""  PC
 SG_ S2P_Cfg13_SW_Ver_Byte11_20 : 16|8@1+ (1,0) [0|255] ""  PC
 SG_ S2P_Cfg13_SW_Ver_Byte12_20 : 24|8@1+ (1,0) [0|255] ""  PC
 SG_ S2P_Cfg13_SW_Ver_Byte13_20 : 32|8@1+ (1,0) [0|255] ""  PC
 SG_ S2P_Cfg13_SW_Ver_Byte14_20 : 40|8@1+ (1,0) [0|255] ""  PC
 SG_ S2P_Cfg13_SW_Ver_Byte15_20 : 48|8@1+ (1,0) [0|255] ""  PC
 SG_ S2P_Cfg13_SW_Ver_Byte16_20 : 56|8@1+ (1,0) [0|255] ""  PC

BO_ 2418667093 S2P_Cfg13__21: 8 SBMU
 SG_ S2P_Cfg13_SW_Ver_Byte9_21 : 0|8@1+ (1,0) [0|255] ""  PC
 SG_ S2P_Cfg13_SW_Ver_Byte10_21 : 8|8@1+ (1,0) [0|255] ""  PC
 SG_ S2P_Cfg13_SW_Ver_Byte11_21 : 16|8@1+ (1,0) [0|255] ""  PC
 SG_ S2P_Cfg13_SW_Ver_Byte12_21 : 24|8@1+ (1,0) [0|255] ""  PC
 SG_ S2P_Cfg13_SW_Ver_Byte13_21 : 32|8@1+ (1,0) [0|255] ""  PC
 SG_ S2P_Cfg13_SW_Ver_Byte14_21 : 40|8@1+ (1,0) [0|255] ""  PC
 SG_ S2P_Cfg13_SW_Ver_Byte15_21 : 48|8@1+ (1,0) [0|255] ""  PC
 SG_ S2P_Cfg13_SW_Ver_Byte16_21 : 56|8@1+ (1,0) [0|255] ""  PC

BO_ 2418667094 S2P_Cfg13__22: 8 SBMU
 SG_ S2P_Cfg13_SW_Ver_Byte9_22 : 0|8@1+ (1,0) [0|255] ""  PC
 SG_ S2P_Cfg13_SW_Ver_Byte10_22 : 8|8@1+ (1,0) [0|255] ""  PC
 SG_ S2P_Cfg13_SW_Ver_Byte11_22 : 16|8@1+ (1,0) [0|255] ""  PC
 SG_ S2P_Cfg13_SW_Ver_Byte12_22 : 24|8@1+ (1,0) [0|255] ""  PC
 SG_ S2P_Cfg13_SW_Ver_Byte13_22 : 32|8@1+ (1,0) [0|255] ""  PC
 SG_ S2P_Cfg13_SW_Ver_Byte14_22 : 40|8@1+ (1,0) [0|255] ""  PC
 SG_ S2P_Cfg13_SW_Ver_Byte15_22 : 48|8@1+ (1,0) [0|255] ""  PC
 SG_ S2P_Cfg13_SW_Ver_Byte16_22 : 56|8@1+ (1,0) [0|255] ""  PC

BO_ 2418667095 S2P_Cfg13__23: 8 SBMU
 SG_ S2P_Cfg13_SW_Ver_Byte9_23 : 0|8@1+ (1,0) [0|255] ""  PC
 SG_ S2P_Cfg13_SW_Ver_Byte10_23 : 8|8@1+ (1,0) [0|255] ""  PC
 SG_ S2P_Cfg13_SW_Ver_Byte11_23 : 16|8@1+ (1,0) [0|255] ""  PC
 SG_ S2P_Cfg13_SW_Ver_Byte12_23 : 24|8@1+ (1,0) [0|255] ""  PC
 SG_ S2P_Cfg13_SW_Ver_Byte13_23 : 32|8@1+ (1,0) [0|255] ""  PC
 SG_ S2P_Cfg13_SW_Ver_Byte14_23 : 40|8@1+ (1,0) [0|255] ""  PC
 SG_ S2P_Cfg13_SW_Ver_Byte15_23 : 48|8@1+ (1,0) [0|255] ""  PC
 SG_ S2P_Cfg13_SW_Ver_Byte16_23 : 56|8@1+ (1,0) [0|255] ""  PC

BO_ 2418667096 S2P_Cfg13__24: 8 SBMU
 SG_ S2P_Cfg13_SW_Ver_Byte9_24 : 0|8@1+ (1,0) [0|255] ""  PC
 SG_ S2P_Cfg13_SW_Ver_Byte10_24 : 8|8@1+ (1,0) [0|255] ""  PC
 SG_ S2P_Cfg13_SW_Ver_Byte11_24 : 16|8@1+ (1,0) [0|255] ""  PC
 SG_ S2P_Cfg13_SW_Ver_Byte12_24 : 24|8@1+ (1,0) [0|255] ""  PC
 SG_ S2P_Cfg13_SW_Ver_Byte13_24 : 32|8@1+ (1,0) [0|255] ""  PC
 SG_ S2P_Cfg13_SW_Ver_Byte14_24 : 40|8@1+ (1,0) [0|255] ""  PC
 SG_ S2P_Cfg13_SW_Ver_Byte15_24 : 48|8@1+ (1,0) [0|255] ""  PC
 SG_ S2P_Cfg13_SW_Ver_Byte16_24 : 56|8@1+ (1,0) [0|255] ""  PC

BO_ 2418667097 S2P_Cfg13__25: 8 SBMU
 SG_ S2P_Cfg13_SW_Ver_Byte9_25 : 0|8@1+ (1,0) [0|255] ""  PC
 SG_ S2P_Cfg13_SW_Ver_Byte10_25 : 8|8@1+ (1,0) [0|255] ""  PC
 SG_ S2P_Cfg13_SW_Ver_Byte11_25 : 16|8@1+ (1,0) [0|255] ""  PC
 SG_ S2P_Cfg13_SW_Ver_Byte12_25 : 24|8@1+ (1,0) [0|255] ""  PC
 SG_ S2P_Cfg13_SW_Ver_Byte13_25 : 32|8@1+ (1,0) [0|255] ""  PC
 SG_ S2P_Cfg13_SW_Ver_Byte14_25 : 40|8@1+ (1,0) [0|255] ""  PC
 SG_ S2P_Cfg13_SW_Ver_Byte15_25 : 48|8@1+ (1,0) [0|255] ""  PC
 SG_ S2P_Cfg13_SW_Ver_Byte16_25 : 56|8@1+ (1,0) [0|255] ""  PC

BO_ 2418667098 S2P_Cfg13__26: 8 SBMU
 SG_ S2P_Cfg13_SW_Ver_Byte9_26 : 0|8@1+ (1,0) [0|255] ""  PC
 SG_ S2P_Cfg13_SW_Ver_Byte10_26 : 8|8@1+ (1,0) [0|255] ""  PC
 SG_ S2P_Cfg13_SW_Ver_Byte11_26 : 16|8@1+ (1,0) [0|255] ""  PC
 SG_ S2P_Cfg13_SW_Ver_Byte12_26 : 24|8@1+ (1,0) [0|255] ""  PC
 SG_ S2P_Cfg13_SW_Ver_Byte13_26 : 32|8@1+ (1,0) [0|255] ""  PC
 SG_ S2P_Cfg13_SW_Ver_Byte14_26 : 40|8@1+ (1,0) [0|255] ""  PC
 SG_ S2P_Cfg13_SW_Ver_Byte15_26 : 48|8@1+ (1,0) [0|255] ""  PC
 SG_ S2P_Cfg13_SW_Ver_Byte16_26 : 56|8@1+ (1,0) [0|255] ""  PC

BO_ 2418667099 S2P_Cfg13__27: 8 SBMU
 SG_ S2P_Cfg13_SW_Ver_Byte9_27 : 0|8@1+ (1,0) [0|255] ""  PC
 SG_ S2P_Cfg13_SW_Ver_Byte10_27 : 8|8@1+ (1,0) [0|255] ""  PC
 SG_ S2P_Cfg13_SW_Ver_Byte11_27 : 16|8@1+ (1,0) [0|255] ""  PC
 SG_ S2P_Cfg13_SW_Ver_Byte12_27 : 24|8@1+ (1,0) [0|255] ""  PC
 SG_ S2P_Cfg13_SW_Ver_Byte13_27 : 32|8@1+ (1,0) [0|255] ""  PC
 SG_ S2P_Cfg13_SW_Ver_Byte14_27 : 40|8@1+ (1,0) [0|255] ""  PC
 SG_ S2P_Cfg13_SW_Ver_Byte15_27 : 48|8@1+ (1,0) [0|255] ""  PC
 SG_ S2P_Cfg13_SW_Ver_Byte16_27 : 56|8@1+ (1,0) [0|255] ""  PC

BO_ 2418667100 S2P_Cfg13__28: 8 SBMU
 SG_ S2P_Cfg13_SW_Ver_Byte9_28 : 0|8@1+ (1,0) [0|255] ""  PC
 SG_ S2P_Cfg13_SW_Ver_Byte10_28 : 8|8@1+ (1,0) [0|255] ""  PC
 SG_ S2P_Cfg13_SW_Ver_Byte11_28 : 16|8@1+ (1,0) [0|255] ""  PC
 SG_ S2P_Cfg13_SW_Ver_Byte12_28 : 24|8@1+ (1,0) [0|255] ""  PC
 SG_ S2P_Cfg13_SW_Ver_Byte13_28 : 32|8@1+ (1,0) [0|255] ""  PC
 SG_ S2P_Cfg13_SW_Ver_Byte14_28 : 40|8@1+ (1,0) [0|255] ""  PC
 SG_ S2P_Cfg13_SW_Ver_Byte15_28 : 48|8@1+ (1,0) [0|255] ""  PC
 SG_ S2P_Cfg13_SW_Ver_Byte16_28 : 56|8@1+ (1,0) [0|255] ""  PC

BO_ 2418667101 S2P_Cfg13__29: 8 SBMU
 SG_ S2P_Cfg13_SW_Ver_Byte9_29 : 0|8@1+ (1,0) [0|255] ""  PC
 SG_ S2P_Cfg13_SW_Ver_Byte10_29 : 8|8@1+ (1,0) [0|255] ""  PC
 SG_ S2P_Cfg13_SW_Ver_Byte11_29 : 16|8@1+ (1,0) [0|255] ""  PC
 SG_ S2P_Cfg13_SW_Ver_Byte12_29 : 24|8@1+ (1,0) [0|255] ""  PC
 SG_ S2P_Cfg13_SW_Ver_Byte13_29 : 32|8@1+ (1,0) [0|255] ""  PC
 SG_ S2P_Cfg13_SW_Ver_Byte14_29 : 40|8@1+ (1,0) [0|255] ""  PC
 SG_ S2P_Cfg13_SW_Ver_Byte15_29 : 48|8@1+ (1,0) [0|255] ""  PC
 SG_ S2P_Cfg13_SW_Ver_Byte16_29 : 56|8@1+ (1,0) [0|255] ""  PC

BO_ 2418667102 S2P_Cfg13__30: 8 SBMU
 SG_ S2P_Cfg13_SW_Ver_Byte9_30 : 0|8@1+ (1,0) [0|255] ""  PC
 SG_ S2P_Cfg13_SW_Ver_Byte10_30 : 8|8@1+ (1,0) [0|255] ""  PC
 SG_ S2P_Cfg13_SW_Ver_Byte11_30 : 16|8@1+ (1,0) [0|255] ""  PC
 SG_ S2P_Cfg13_SW_Ver_Byte12_30 : 24|8@1+ (1,0) [0|255] ""  PC
 SG_ S2P_Cfg13_SW_Ver_Byte13_30 : 32|8@1+ (1,0) [0|255] ""  PC
 SG_ S2P_Cfg13_SW_Ver_Byte14_30 : 40|8@1+ (1,0) [0|255] ""  PC
 SG_ S2P_Cfg13_SW_Ver_Byte15_30 : 48|8@1+ (1,0) [0|255] ""  PC
 SG_ S2P_Cfg13_SW_Ver_Byte16_30 : 56|8@1+ (1,0) [0|255] ""  PC

BO_ 2418667103 S2P_Cfg13__31: 8 SBMU
 SG_ S2P_Cfg13_SW_Ver_Byte9_31 : 0|8@1+ (1,0) [0|255] ""  PC
 SG_ S2P_Cfg13_SW_Ver_Byte10_31 : 8|8@1+ (1,0) [0|255] ""  PC
 SG_ S2P_Cfg13_SW_Ver_Byte11_31 : 16|8@1+ (1,0) [0|255] ""  PC
 SG_ S2P_Cfg13_SW_Ver_Byte12_31 : 24|8@1+ (1,0) [0|255] ""  PC
 SG_ S2P_Cfg13_SW_Ver_Byte13_31 : 32|8@1+ (1,0) [0|255] ""  PC
 SG_ S2P_Cfg13_SW_Ver_Byte14_31 : 40|8@1+ (1,0) [0|255] ""  PC
 SG_ S2P_Cfg13_SW_Ver_Byte15_31 : 48|8@1+ (1,0) [0|255] ""  PC
 SG_ S2P_Cfg13_SW_Ver_Byte16_31 : 56|8@1+ (1,0) [0|255] ""  PC

BO_ 2418667104 S2P_Cfg13__32: 8 SBMU
 SG_ S2P_Cfg13_SW_Ver_Byte9_32 : 0|8@1+ (1,0) [0|255] ""  PC
 SG_ S2P_Cfg13_SW_Ver_Byte10_32 : 8|8@1+ (1,0) [0|255] ""  PC
 SG_ S2P_Cfg13_SW_Ver_Byte11_32 : 16|8@1+ (1,0) [0|255] ""  PC
 SG_ S2P_Cfg13_SW_Ver_Byte12_32 : 24|8@1+ (1,0) [0|255] ""  PC
 SG_ S2P_Cfg13_SW_Ver_Byte13_32 : 32|8@1+ (1,0) [0|255] ""  PC
 SG_ S2P_Cfg13_SW_Ver_Byte14_32 : 40|8@1+ (1,0) [0|255] ""  PC
 SG_ S2P_Cfg13_SW_Ver_Byte15_32 : 48|8@1+ (1,0) [0|255] ""  PC
 SG_ S2P_Cfg13_SW_Ver_Byte16_32 : 56|8@1+ (1,0) [0|255] ""  PC

BO_ 2418667105 S2P_Cfg13__33: 8 SBMU
 SG_ S2P_Cfg13_SW_Ver_Byte9_33 : 0|8@1+ (1,0) [0|255] ""  PC
 SG_ S2P_Cfg13_SW_Ver_Byte10_33 : 8|8@1+ (1,0) [0|255] ""  PC
 SG_ S2P_Cfg13_SW_Ver_Byte11_33 : 16|8@1+ (1,0) [0|255] ""  PC
 SG_ S2P_Cfg13_SW_Ver_Byte12_33 : 24|8@1+ (1,0) [0|255] ""  PC
 SG_ S2P_Cfg13_SW_Ver_Byte13_33 : 32|8@1+ (1,0) [0|255] ""  PC
 SG_ S2P_Cfg13_SW_Ver_Byte14_33 : 40|8@1+ (1,0) [0|255] ""  PC
 SG_ S2P_Cfg13_SW_Ver_Byte15_33 : 48|8@1+ (1,0) [0|255] ""  PC
 SG_ S2P_Cfg13_SW_Ver_Byte16_33 : 56|8@1+ (1,0) [0|255] ""  PC

BO_ 2418667106 S2P_Cfg13__34: 8 SBMU
 SG_ S2P_Cfg13_SW_Ver_Byte9_34 : 0|8@1+ (1,0) [0|255] ""  PC
 SG_ S2P_Cfg13_SW_Ver_Byte10_34 : 8|8@1+ (1,0) [0|255] ""  PC
 SG_ S2P_Cfg13_SW_Ver_Byte11_34 : 16|8@1+ (1,0) [0|255] ""  PC
 SG_ S2P_Cfg13_SW_Ver_Byte12_34 : 24|8@1+ (1,0) [0|255] ""  PC
 SG_ S2P_Cfg13_SW_Ver_Byte13_34 : 32|8@1+ (1,0) [0|255] ""  PC
 SG_ S2P_Cfg13_SW_Ver_Byte14_34 : 40|8@1+ (1,0) [0|255] ""  PC
 SG_ S2P_Cfg13_SW_Ver_Byte15_34 : 48|8@1+ (1,0) [0|255] ""  PC
 SG_ S2P_Cfg13_SW_Ver_Byte16_34 : 56|8@1+ (1,0) [0|255] ""  PC

BO_ 2418667107 S2P_Cfg13__35: 8 SBMU
 SG_ S2P_Cfg13_SW_Ver_Byte9_35 : 0|8@1+ (1,0) [0|255] ""  PC
 SG_ S2P_Cfg13_SW_Ver_Byte10_35 : 8|8@1+ (1,0) [0|255] ""  PC
 SG_ S2P_Cfg13_SW_Ver_Byte11_35 : 16|8@1+ (1,0) [0|255] ""  PC
 SG_ S2P_Cfg13_SW_Ver_Byte12_35 : 24|8@1+ (1,0) [0|255] ""  PC
 SG_ S2P_Cfg13_SW_Ver_Byte13_35 : 32|8@1+ (1,0) [0|255] ""  PC
 SG_ S2P_Cfg13_SW_Ver_Byte14_35 : 40|8@1+ (1,0) [0|255] ""  PC
 SG_ S2P_Cfg13_SW_Ver_Byte15_35 : 48|8@1+ (1,0) [0|255] ""  PC
 SG_ S2P_Cfg13_SW_Ver_Byte16_35 : 56|8@1+ (1,0) [0|255] ""  PC

BO_ 2418667108 S2P_Cfg13__36: 8 SBMU
 SG_ S2P_Cfg13_SW_Ver_Byte9_36 : 0|8@1+ (1,0) [0|255] ""  PC
 SG_ S2P_Cfg13_SW_Ver_Byte10_36 : 8|8@1+ (1,0) [0|255] ""  PC
 SG_ S2P_Cfg13_SW_Ver_Byte11_36 : 16|8@1+ (1,0) [0|255] ""  PC
 SG_ S2P_Cfg13_SW_Ver_Byte12_36 : 24|8@1+ (1,0) [0|255] ""  PC
 SG_ S2P_Cfg13_SW_Ver_Byte13_36 : 32|8@1+ (1,0) [0|255] ""  PC
 SG_ S2P_Cfg13_SW_Ver_Byte14_36 : 40|8@1+ (1,0) [0|255] ""  PC
 SG_ S2P_Cfg13_SW_Ver_Byte15_36 : 48|8@1+ (1,0) [0|255] ""  PC
 SG_ S2P_Cfg13_SW_Ver_Byte16_36 : 56|8@1+ (1,0) [0|255] ""  PC

BO_ 2418667109 S2P_Cfg13__37: 8 SBMU
 SG_ S2P_Cfg13_SW_Ver_Byte9_37 : 0|8@1+ (1,0) [0|255] ""  PC
 SG_ S2P_Cfg13_SW_Ver_Byte10_37 : 8|8@1+ (1,0) [0|255] ""  PC
 SG_ S2P_Cfg13_SW_Ver_Byte11_37 : 16|8@1+ (1,0) [0|255] ""  PC
 SG_ S2P_Cfg13_SW_Ver_Byte12_37 : 24|8@1+ (1,0) [0|255] ""  PC
 SG_ S2P_Cfg13_SW_Ver_Byte13_37 : 32|8@1+ (1,0) [0|255] ""  PC
 SG_ S2P_Cfg13_SW_Ver_Byte14_37 : 40|8@1+ (1,0) [0|255] ""  PC
 SG_ S2P_Cfg13_SW_Ver_Byte15_37 : 48|8@1+ (1,0) [0|255] ""  PC
 SG_ S2P_Cfg13_SW_Ver_Byte16_37 : 56|8@1+ (1,0) [0|255] ""  PC

BO_ 2418667110 S2P_Cfg13__38: 8 SBMU
 SG_ S2P_Cfg13_SW_Ver_Byte9_38 : 0|8@1+ (1,0) [0|255] ""  PC
 SG_ S2P_Cfg13_SW_Ver_Byte10_38 : 8|8@1+ (1,0) [0|255] ""  PC
 SG_ S2P_Cfg13_SW_Ver_Byte11_38 : 16|8@1+ (1,0) [0|255] ""  PC
 SG_ S2P_Cfg13_SW_Ver_Byte12_38 : 24|8@1+ (1,0) [0|255] ""  PC
 SG_ S2P_Cfg13_SW_Ver_Byte13_38 : 32|8@1+ (1,0) [0|255] ""  PC
 SG_ S2P_Cfg13_SW_Ver_Byte14_38 : 40|8@1+ (1,0) [0|255] ""  PC
 SG_ S2P_Cfg13_SW_Ver_Byte15_38 : 48|8@1+ (1,0) [0|255] ""  PC
 SG_ S2P_Cfg13_SW_Ver_Byte16_38 : 56|8@1+ (1,0) [0|255] ""  PC

BO_ 2418667111 S2P_Cfg13__39: 8 SBMU
 SG_ S2P_Cfg13_SW_Ver_Byte9_39 : 0|8@1+ (1,0) [0|255] ""  PC
 SG_ S2P_Cfg13_SW_Ver_Byte10_39 : 8|8@1+ (1,0) [0|255] ""  PC
 SG_ S2P_Cfg13_SW_Ver_Byte11_39 : 16|8@1+ (1,0) [0|255] ""  PC
 SG_ S2P_Cfg13_SW_Ver_Byte12_39 : 24|8@1+ (1,0) [0|255] ""  PC
 SG_ S2P_Cfg13_SW_Ver_Byte13_39 : 32|8@1+ (1,0) [0|255] ""  PC
 SG_ S2P_Cfg13_SW_Ver_Byte14_39 : 40|8@1+ (1,0) [0|255] ""  PC
 SG_ S2P_Cfg13_SW_Ver_Byte15_39 : 48|8@1+ (1,0) [0|255] ""  PC
 SG_ S2P_Cfg13_SW_Ver_Byte16_39 : 56|8@1+ (1,0) [0|255] ""  PC

BO_ 2418667112 S2P_Cfg13__40: 8 SBMU
 SG_ S2P_Cfg13_SW_Ver_Byte9_40 : 0|8@1+ (1,0) [0|255] ""  PC
 SG_ S2P_Cfg13_SW_Ver_Byte10_40 : 8|8@1+ (1,0) [0|255] ""  PC
 SG_ S2P_Cfg13_SW_Ver_Byte11_40 : 16|8@1+ (1,0) [0|255] ""  PC
 SG_ S2P_Cfg13_SW_Ver_Byte12_40 : 24|8@1+ (1,0) [0|255] ""  PC
 SG_ S2P_Cfg13_SW_Ver_Byte13_40 : 32|8@1+ (1,0) [0|255] ""  PC
 SG_ S2P_Cfg13_SW_Ver_Byte14_40 : 40|8@1+ (1,0) [0|255] ""  PC
 SG_ S2P_Cfg13_SW_Ver_Byte15_40 : 48|8@1+ (1,0) [0|255] ""  PC
 SG_ S2P_Cfg13_SW_Ver_Byte16_40 : 56|8@1+ (1,0) [0|255] ""  PC

BO_ 2418667113 S2P_Cfg13__41: 8 SBMU
 SG_ S2P_Cfg13_SW_Ver_Byte9_41 : 0|8@1+ (1,0) [0|255] ""  PC
 SG_ S2P_Cfg13_SW_Ver_Byte10_41 : 8|8@1+ (1,0) [0|255] ""  PC
 SG_ S2P_Cfg13_SW_Ver_Byte11_41 : 16|8@1+ (1,0) [0|255] ""  PC
 SG_ S2P_Cfg13_SW_Ver_Byte12_41 : 24|8@1+ (1,0) [0|255] ""  PC
 SG_ S2P_Cfg13_SW_Ver_Byte13_41 : 32|8@1+ (1,0) [0|255] ""  PC
 SG_ S2P_Cfg13_SW_Ver_Byte14_41 : 40|8@1+ (1,0) [0|255] ""  PC
 SG_ S2P_Cfg13_SW_Ver_Byte15_41 : 48|8@1+ (1,0) [0|255] ""  PC
 SG_ S2P_Cfg13_SW_Ver_Byte16_41 : 56|8@1+ (1,0) [0|255] ""  PC

BO_ 2418667114 S2P_Cfg13__42: 8 SBMU
 SG_ S2P_Cfg13_SW_Ver_Byte9_42 : 0|8@1+ (1,0) [0|255] ""  PC
 SG_ S2P_Cfg13_SW_Ver_Byte10_42 : 8|8@1+ (1,0) [0|255] ""  PC
 SG_ S2P_Cfg13_SW_Ver_Byte11_42 : 16|8@1+ (1,0) [0|255] ""  PC
 SG_ S2P_Cfg13_SW_Ver_Byte12_42 : 24|8@1+ (1,0) [0|255] ""  PC
 SG_ S2P_Cfg13_SW_Ver_Byte13_42 : 32|8@1+ (1,0) [0|255] ""  PC
 SG_ S2P_Cfg13_SW_Ver_Byte14_42 : 40|8@1+ (1,0) [0|255] ""  PC
 SG_ S2P_Cfg13_SW_Ver_Byte15_42 : 48|8@1+ (1,0) [0|255] ""  PC
 SG_ S2P_Cfg13_SW_Ver_Byte16_42 : 56|8@1+ (1,0) [0|255] ""  PC

BO_ 2418667115 S2P_Cfg13__43: 8 SBMU
 SG_ S2P_Cfg13_SW_Ver_Byte9_43 : 0|8@1+ (1,0) [0|255] ""  PC
 SG_ S2P_Cfg13_SW_Ver_Byte10_43 : 8|8@1+ (1,0) [0|255] ""  PC
 SG_ S2P_Cfg13_SW_Ver_Byte11_43 : 16|8@1+ (1,0) [0|255] ""  PC
 SG_ S2P_Cfg13_SW_Ver_Byte12_43 : 24|8@1+ (1,0) [0|255] ""  PC
 SG_ S2P_Cfg13_SW_Ver_Byte13_43 : 32|8@1+ (1,0) [0|255] ""  PC
 SG_ S2P_Cfg13_SW_Ver_Byte14_43 : 40|8@1+ (1,0) [0|255] ""  PC
 SG_ S2P_Cfg13_SW_Ver_Byte15_43 : 48|8@1+ (1,0) [0|255] ""  PC
 SG_ S2P_Cfg13_SW_Ver_Byte16_43 : 56|8@1+ (1,0) [0|255] ""  PC

BO_ 2418667116 S2P_Cfg13__44: 8 SBMU
 SG_ S2P_Cfg13_SW_Ver_Byte9_44 : 0|8@1+ (1,0) [0|255] ""  PC
 SG_ S2P_Cfg13_SW_Ver_Byte10_44 : 8|8@1+ (1,0) [0|255] ""  PC
 SG_ S2P_Cfg13_SW_Ver_Byte11_44 : 16|8@1+ (1,0) [0|255] ""  PC
 SG_ S2P_Cfg13_SW_Ver_Byte12_44 : 24|8@1+ (1,0) [0|255] ""  PC
 SG_ S2P_Cfg13_SW_Ver_Byte13_44 : 32|8@1+ (1,0) [0|255] ""  PC
 SG_ S2P_Cfg13_SW_Ver_Byte14_44 : 40|8@1+ (1,0) [0|255] ""  PC
 SG_ S2P_Cfg13_SW_Ver_Byte15_44 : 48|8@1+ (1,0) [0|255] ""  PC
 SG_ S2P_Cfg13_SW_Ver_Byte16_44 : 56|8@1+ (1,0) [0|255] ""  PC

BO_ 2418667117 S2P_Cfg13__45: 8 SBMU
 SG_ S2P_Cfg13_SW_Ver_Byte9_45 : 0|8@1+ (1,0) [0|255] ""  PC
 SG_ S2P_Cfg13_SW_Ver_Byte10_45 : 8|8@1+ (1,0) [0|255] ""  PC
 SG_ S2P_Cfg13_SW_Ver_Byte11_45 : 16|8@1+ (1,0) [0|255] ""  PC
 SG_ S2P_Cfg13_SW_Ver_Byte12_45 : 24|8@1+ (1,0) [0|255] ""  PC
 SG_ S2P_Cfg13_SW_Ver_Byte13_45 : 32|8@1+ (1,0) [0|255] ""  PC
 SG_ S2P_Cfg13_SW_Ver_Byte14_45 : 40|8@1+ (1,0) [0|255] ""  PC
 SG_ S2P_Cfg13_SW_Ver_Byte15_45 : 48|8@1+ (1,0) [0|255] ""  PC
 SG_ S2P_Cfg13_SW_Ver_Byte16_45 : 56|8@1+ (1,0) [0|255] ""  PC

BO_ 2418667118 S2P_Cfg13__46: 8 SBMU
 SG_ S2P_Cfg13_SW_Ver_Byte9_46 : 0|8@1+ (1,0) [0|255] ""  PC
 SG_ S2P_Cfg13_SW_Ver_Byte10_46 : 8|8@1+ (1,0) [0|255] ""  PC
 SG_ S2P_Cfg13_SW_Ver_Byte11_46 : 16|8@1+ (1,0) [0|255] ""  PC
 SG_ S2P_Cfg13_SW_Ver_Byte12_46 : 24|8@1+ (1,0) [0|255] ""  PC
 SG_ S2P_Cfg13_SW_Ver_Byte13_46 : 32|8@1+ (1,0) [0|255] ""  PC
 SG_ S2P_Cfg13_SW_Ver_Byte14_46 : 40|8@1+ (1,0) [0|255] ""  PC
 SG_ S2P_Cfg13_SW_Ver_Byte15_46 : 48|8@1+ (1,0) [0|255] ""  PC
 SG_ S2P_Cfg13_SW_Ver_Byte16_46 : 56|8@1+ (1,0) [0|255] ""  PC

BO_ 2418667119 S2P_Cfg13__47: 8 SBMU
 SG_ S2P_Cfg13_SW_Ver_Byte9_47 : 0|8@1+ (1,0) [0|255] ""  PC
 SG_ S2P_Cfg13_SW_Ver_Byte10_47 : 8|8@1+ (1,0) [0|255] ""  PC
 SG_ S2P_Cfg13_SW_Ver_Byte11_47 : 16|8@1+ (1,0) [0|255] ""  PC
 SG_ S2P_Cfg13_SW_Ver_Byte12_47 : 24|8@1+ (1,0) [0|255] ""  PC
 SG_ S2P_Cfg13_SW_Ver_Byte13_47 : 32|8@1+ (1,0) [0|255] ""  PC
 SG_ S2P_Cfg13_SW_Ver_Byte14_47 : 40|8@1+ (1,0) [0|255] ""  PC
 SG_ S2P_Cfg13_SW_Ver_Byte15_47 : 48|8@1+ (1,0) [0|255] ""  PC
 SG_ S2P_Cfg13_SW_Ver_Byte16_47 : 56|8@1+ (1,0) [0|255] ""  PC

BO_ 2418667120 S2P_Cfg13__48: 8 SBMU
 SG_ S2P_Cfg13_SW_Ver_Byte9_48 : 0|8@1+ (1,0) [0|255] ""  PC
 SG_ S2P_Cfg13_SW_Ver_Byte10_48 : 8|8@1+ (1,0) [0|255] ""  PC
 SG_ S2P_Cfg13_SW_Ver_Byte11_48 : 16|8@1+ (1,0) [0|255] ""  PC
 SG_ S2P_Cfg13_SW_Ver_Byte12_48 : 24|8@1+ (1,0) [0|255] ""  PC
 SG_ S2P_Cfg13_SW_Ver_Byte13_48 : 32|8@1+ (1,0) [0|255] ""  PC
 SG_ S2P_Cfg13_SW_Ver_Byte14_48 : 40|8@1+ (1,0) [0|255] ""  PC
 SG_ S2P_Cfg13_SW_Ver_Byte15_48 : 48|8@1+ (1,0) [0|255] ""  PC
 SG_ S2P_Cfg13_SW_Ver_Byte16_48 : 56|8@1+ (1,0) [0|255] ""  PC

BO_ 2418667121 S2P_Cfg13__49: 8 SBMU
 SG_ S2P_Cfg13_SW_Ver_Byte9_49 : 0|8@1+ (1,0) [0|255] ""  PC
 SG_ S2P_Cfg13_SW_Ver_Byte10_49 : 8|8@1+ (1,0) [0|255] ""  PC
 SG_ S2P_Cfg13_SW_Ver_Byte11_49 : 16|8@1+ (1,0) [0|255] ""  PC
 SG_ S2P_Cfg13_SW_Ver_Byte12_49 : 24|8@1+ (1,0) [0|255] ""  PC
 SG_ S2P_Cfg13_SW_Ver_Byte13_49 : 32|8@1+ (1,0) [0|255] ""  PC
 SG_ S2P_Cfg13_SW_Ver_Byte14_49 : 40|8@1+ (1,0) [0|255] ""  PC
 SG_ S2P_Cfg13_SW_Ver_Byte15_49 : 48|8@1+ (1,0) [0|255] ""  PC
 SG_ S2P_Cfg13_SW_Ver_Byte16_49 : 56|8@1+ (1,0) [0|255] ""  PC

BO_ 2418667122 S2P_Cfg13__50: 8 SBMU
 SG_ S2P_Cfg13_SW_Ver_Byte9_50 : 0|8@1+ (1,0) [0|255] ""  PC
 SG_ S2P_Cfg13_SW_Ver_Byte10_50 : 8|8@1+ (1,0) [0|255] ""  PC
 SG_ S2P_Cfg13_SW_Ver_Byte11_50 : 16|8@1+ (1,0) [0|255] ""  PC
 SG_ S2P_Cfg13_SW_Ver_Byte12_50 : 24|8@1+ (1,0) [0|255] ""  PC
 SG_ S2P_Cfg13_SW_Ver_Byte13_50 : 32|8@1+ (1,0) [0|255] ""  PC
 SG_ S2P_Cfg13_SW_Ver_Byte14_50 : 40|8@1+ (1,0) [0|255] ""  PC
 SG_ S2P_Cfg13_SW_Ver_Byte15_50 : 48|8@1+ (1,0) [0|255] ""  PC
 SG_ S2P_Cfg13_SW_Ver_Byte16_50 : 56|8@1+ (1,0) [0|255] ""  PC

BO_ 2418667123 S2P_Cfg13__51: 8 SBMU
 SG_ S2P_Cfg13_SW_Ver_Byte9_51 : 0|8@1+ (1,0) [0|255] ""  PC
 SG_ S2P_Cfg13_SW_Ver_Byte10_51 : 8|8@1+ (1,0) [0|255] ""  PC
 SG_ S2P_Cfg13_SW_Ver_Byte11_51 : 16|8@1+ (1,0) [0|255] ""  PC
 SG_ S2P_Cfg13_SW_Ver_Byte12_51 : 24|8@1+ (1,0) [0|255] ""  PC
 SG_ S2P_Cfg13_SW_Ver_Byte13_51 : 32|8@1+ (1,0) [0|255] ""  PC
 SG_ S2P_Cfg13_SW_Ver_Byte14_51 : 40|8@1+ (1,0) [0|255] ""  PC
 SG_ S2P_Cfg13_SW_Ver_Byte15_51 : 48|8@1+ (1,0) [0|255] ""  PC
 SG_ S2P_Cfg13_SW_Ver_Byte16_51 : 56|8@1+ (1,0) [0|255] ""  PC

BO_ 2418667124 S2P_Cfg13__52: 8 SBMU
 SG_ S2P_Cfg13_SW_Ver_Byte9_52 : 0|8@1+ (1,0) [0|255] ""  PC
 SG_ S2P_Cfg13_SW_Ver_Byte10_52 : 8|8@1+ (1,0) [0|255] ""  PC
 SG_ S2P_Cfg13_SW_Ver_Byte11_52 : 16|8@1+ (1,0) [0|255] ""  PC
 SG_ S2P_Cfg13_SW_Ver_Byte12_52 : 24|8@1+ (1,0) [0|255] ""  PC
 SG_ S2P_Cfg13_SW_Ver_Byte13_52 : 32|8@1+ (1,0) [0|255] ""  PC
 SG_ S2P_Cfg13_SW_Ver_Byte14_52 : 40|8@1+ (1,0) [0|255] ""  PC
 SG_ S2P_Cfg13_SW_Ver_Byte15_52 : 48|8@1+ (1,0) [0|255] ""  PC
 SG_ S2P_Cfg13_SW_Ver_Byte16_52 : 56|8@1+ (1,0) [0|255] ""  PC

BO_ 2418667125 S2P_Cfg13__53: 8 SBMU
 SG_ S2P_Cfg13_SW_Ver_Byte9_53 : 0|8@1+ (1,0) [0|255] ""  PC
 SG_ S2P_Cfg13_SW_Ver_Byte10_53 : 8|8@1+ (1,0) [0|255] ""  PC
 SG_ S2P_Cfg13_SW_Ver_Byte11_53 : 16|8@1+ (1,0) [0|255] ""  PC
 SG_ S2P_Cfg13_SW_Ver_Byte12_53 : 24|8@1+ (1,0) [0|255] ""  PC
 SG_ S2P_Cfg13_SW_Ver_Byte13_53 : 32|8@1+ (1,0) [0|255] ""  PC
 SG_ S2P_Cfg13_SW_Ver_Byte14_53 : 40|8@1+ (1,0) [0|255] ""  PC
 SG_ S2P_Cfg13_SW_Ver_Byte15_53 : 48|8@1+ (1,0) [0|255] ""  PC
 SG_ S2P_Cfg13_SW_Ver_Byte16_53 : 56|8@1+ (1,0) [0|255] ""  PC

BO_ 2418667126 S2P_Cfg13__54: 8 SBMU
 SG_ S2P_Cfg13_SW_Ver_Byte9_54 : 0|8@1+ (1,0) [0|255] ""  PC
 SG_ S2P_Cfg13_SW_Ver_Byte10_54 : 8|8@1+ (1,0) [0|255] ""  PC
 SG_ S2P_Cfg13_SW_Ver_Byte11_54 : 16|8@1+ (1,0) [0|255] ""  PC
 SG_ S2P_Cfg13_SW_Ver_Byte12_54 : 24|8@1+ (1,0) [0|255] ""  PC
 SG_ S2P_Cfg13_SW_Ver_Byte13_54 : 32|8@1+ (1,0) [0|255] ""  PC
 SG_ S2P_Cfg13_SW_Ver_Byte14_54 : 40|8@1+ (1,0) [0|255] ""  PC
 SG_ S2P_Cfg13_SW_Ver_Byte15_54 : 48|8@1+ (1,0) [0|255] ""  PC
 SG_ S2P_Cfg13_SW_Ver_Byte16_54 : 56|8@1+ (1,0) [0|255] ""  PC

BO_ 2418667127 S2P_Cfg13__55: 8 SBMU
 SG_ S2P_Cfg13_SW_Ver_Byte9_55 : 0|8@1+ (1,0) [0|255] ""  PC
 SG_ S2P_Cfg13_SW_Ver_Byte10_55 : 8|8@1+ (1,0) [0|255] ""  PC
 SG_ S2P_Cfg13_SW_Ver_Byte11_55 : 16|8@1+ (1,0) [0|255] ""  PC
 SG_ S2P_Cfg13_SW_Ver_Byte12_55 : 24|8@1+ (1,0) [0|255] ""  PC
 SG_ S2P_Cfg13_SW_Ver_Byte13_55 : 32|8@1+ (1,0) [0|255] ""  PC
 SG_ S2P_Cfg13_SW_Ver_Byte14_55 : 40|8@1+ (1,0) [0|255] ""  PC
 SG_ S2P_Cfg13_SW_Ver_Byte15_55 : 48|8@1+ (1,0) [0|255] ""  PC
 SG_ S2P_Cfg13_SW_Ver_Byte16_55 : 56|8@1+ (1,0) [0|255] ""  PC

BO_ 2418667128 S2P_Cfg13__56: 8 SBMU
 SG_ S2P_Cfg13_SW_Ver_Byte9_56 : 0|8@1+ (1,0) [0|255] ""  PC
 SG_ S2P_Cfg13_SW_Ver_Byte10_56 : 8|8@1+ (1,0) [0|255] ""  PC
 SG_ S2P_Cfg13_SW_Ver_Byte11_56 : 16|8@1+ (1,0) [0|255] ""  PC
 SG_ S2P_Cfg13_SW_Ver_Byte12_56 : 24|8@1+ (1,0) [0|255] ""  PC
 SG_ S2P_Cfg13_SW_Ver_Byte13_56 : 32|8@1+ (1,0) [0|255] ""  PC
 SG_ S2P_Cfg13_SW_Ver_Byte14_56 : 40|8@1+ (1,0) [0|255] ""  PC
 SG_ S2P_Cfg13_SW_Ver_Byte15_56 : 48|8@1+ (1,0) [0|255] ""  PC
 SG_ S2P_Cfg13_SW_Ver_Byte16_56 : 56|8@1+ (1,0) [0|255] ""  PC

BO_ 2418667129 S2P_Cfg13__57: 8 SBMU
 SG_ S2P_Cfg13_SW_Ver_Byte9_57 : 0|8@1+ (1,0) [0|255] ""  PC
 SG_ S2P_Cfg13_SW_Ver_Byte10_57 : 8|8@1+ (1,0) [0|255] ""  PC
 SG_ S2P_Cfg13_SW_Ver_Byte11_57 : 16|8@1+ (1,0) [0|255] ""  PC
 SG_ S2P_Cfg13_SW_Ver_Byte12_57 : 24|8@1+ (1,0) [0|255] ""  PC
 SG_ S2P_Cfg13_SW_Ver_Byte13_57 : 32|8@1+ (1,0) [0|255] ""  PC
 SG_ S2P_Cfg13_SW_Ver_Byte14_57 : 40|8@1+ (1,0) [0|255] ""  PC
 SG_ S2P_Cfg13_SW_Ver_Byte15_57 : 48|8@1+ (1,0) [0|255] ""  PC
 SG_ S2P_Cfg13_SW_Ver_Byte16_57 : 56|8@1+ (1,0) [0|255] ""  PC

BO_ 2418667130 S2P_Cfg13__58: 8 SBMU
 SG_ S2P_Cfg13_SW_Ver_Byte9_58 : 0|8@1+ (1,0) [0|255] ""  PC
 SG_ S2P_Cfg13_SW_Ver_Byte10_58 : 8|8@1+ (1,0) [0|255] ""  PC
 SG_ S2P_Cfg13_SW_Ver_Byte11_58 : 16|8@1+ (1,0) [0|255] ""  PC
 SG_ S2P_Cfg13_SW_Ver_Byte12_58 : 24|8@1+ (1,0) [0|255] ""  PC
 SG_ S2P_Cfg13_SW_Ver_Byte13_58 : 32|8@1+ (1,0) [0|255] ""  PC
 SG_ S2P_Cfg13_SW_Ver_Byte14_58 : 40|8@1+ (1,0) [0|255] ""  PC
 SG_ S2P_Cfg13_SW_Ver_Byte15_58 : 48|8@1+ (1,0) [0|255] ""  PC
 SG_ S2P_Cfg13_SW_Ver_Byte16_58 : 56|8@1+ (1,0) [0|255] ""  PC

BO_ 2418667131 S2P_Cfg13__59: 8 SBMU
 SG_ S2P_Cfg13_SW_Ver_Byte9_59 : 0|8@1+ (1,0) [0|255] ""  PC
 SG_ S2P_Cfg13_SW_Ver_Byte10_59 : 8|8@1+ (1,0) [0|255] ""  PC
 SG_ S2P_Cfg13_SW_Ver_Byte11_59 : 16|8@1+ (1,0) [0|255] ""  PC
 SG_ S2P_Cfg13_SW_Ver_Byte12_59 : 24|8@1+ (1,0) [0|255] ""  PC
 SG_ S2P_Cfg13_SW_Ver_Byte13_59 : 32|8@1+ (1,0) [0|255] ""  PC
 SG_ S2P_Cfg13_SW_Ver_Byte14_59 : 40|8@1+ (1,0) [0|255] ""  PC
 SG_ S2P_Cfg13_SW_Ver_Byte15_59 : 48|8@1+ (1,0) [0|255] ""  PC
 SG_ S2P_Cfg13_SW_Ver_Byte16_59 : 56|8@1+ (1,0) [0|255] ""  PC

BO_ 2418667132 S2P_Cfg13__60: 8 SBMU
 SG_ S2P_Cfg13_SW_Ver_Byte9_60 : 0|8@1+ (1,0) [0|255] ""  PC
 SG_ S2P_Cfg13_SW_Ver_Byte10_60 : 8|8@1+ (1,0) [0|255] ""  PC
 SG_ S2P_Cfg13_SW_Ver_Byte11_60 : 16|8@1+ (1,0) [0|255] ""  PC
 SG_ S2P_Cfg13_SW_Ver_Byte12_60 : 24|8@1+ (1,0) [0|255] ""  PC
 SG_ S2P_Cfg13_SW_Ver_Byte13_60 : 32|8@1+ (1,0) [0|255] ""  PC
 SG_ S2P_Cfg13_SW_Ver_Byte14_60 : 40|8@1+ (1,0) [0|255] ""  PC
 SG_ S2P_Cfg13_SW_Ver_Byte15_60 : 48|8@1+ (1,0) [0|255] ""  PC
 SG_ S2P_Cfg13_SW_Ver_Byte16_60 : 56|8@1+ (1,0) [0|255] ""  PC

BO_ 2418667133 S2P_Cfg13__61: 8 SBMU
 SG_ S2P_Cfg13_SW_Ver_Byte9_61 : 0|8@1+ (1,0) [0|255] ""  PC
 SG_ S2P_Cfg13_SW_Ver_Byte10_61 : 8|8@1+ (1,0) [0|255] ""  PC
 SG_ S2P_Cfg13_SW_Ver_Byte11_61 : 16|8@1+ (1,0) [0|255] ""  PC
 SG_ S2P_Cfg13_SW_Ver_Byte12_61 : 24|8@1+ (1,0) [0|255] ""  PC
 SG_ S2P_Cfg13_SW_Ver_Byte13_61 : 32|8@1+ (1,0) [0|255] ""  PC
 SG_ S2P_Cfg13_SW_Ver_Byte14_61 : 40|8@1+ (1,0) [0|255] ""  PC
 SG_ S2P_Cfg13_SW_Ver_Byte15_61 : 48|8@1+ (1,0) [0|255] ""  PC
 SG_ S2P_Cfg13_SW_Ver_Byte16_61 : 56|8@1+ (1,0) [0|255] ""  PC

BO_ 2418667134 S2P_Cfg13__62: 8 SBMU
 SG_ S2P_Cfg13_SW_Ver_Byte9_62 : 0|8@1+ (1,0) [0|255] ""  PC
 SG_ S2P_Cfg13_SW_Ver_Byte10_62 : 8|8@1+ (1,0) [0|255] ""  PC
 SG_ S2P_Cfg13_SW_Ver_Byte11_62 : 16|8@1+ (1,0) [0|255] ""  PC
 SG_ S2P_Cfg13_SW_Ver_Byte12_62 : 24|8@1+ (1,0) [0|255] ""  PC
 SG_ S2P_Cfg13_SW_Ver_Byte13_62 : 32|8@1+ (1,0) [0|255] ""  PC
 SG_ S2P_Cfg13_SW_Ver_Byte14_62 : 40|8@1+ (1,0) [0|255] ""  PC
 SG_ S2P_Cfg13_SW_Ver_Byte15_62 : 48|8@1+ (1,0) [0|255] ""  PC
 SG_ S2P_Cfg13_SW_Ver_Byte16_62 : 56|8@1+ (1,0) [0|255] ""  PC

BO_ 2418667135 S2P_Cfg13__63: 8 SBMU
 SG_ S2P_Cfg13_SW_Ver_Byte9_63 : 0|8@1+ (1,0) [0|255] ""  PC
 SG_ S2P_Cfg13_SW_Ver_Byte10_63 : 8|8@1+ (1,0) [0|255] ""  PC
 SG_ S2P_Cfg13_SW_Ver_Byte11_63 : 16|8@1+ (1,0) [0|255] ""  PC
 SG_ S2P_Cfg13_SW_Ver_Byte12_63 : 24|8@1+ (1,0) [0|255] ""  PC
 SG_ S2P_Cfg13_SW_Ver_Byte13_63 : 32|8@1+ (1,0) [0|255] ""  PC
 SG_ S2P_Cfg13_SW_Ver_Byte14_63 : 40|8@1+ (1,0) [0|255] ""  PC
 SG_ S2P_Cfg13_SW_Ver_Byte15_63 : 48|8@1+ (1,0) [0|255] ""  PC
 SG_ S2P_Cfg13_SW_Ver_Byte16_63 : 56|8@1+ (1,0) [0|255] ""  PC

BO_ 2483285649 E2P_Cfg1__01: 8 ETH
 SG_ E2P_Cfg1_SW_Ver_Byte1 : 0|8@1+ (1,0) [0|255] ""  PC
 SG_ E2P_Cfg1_SW_Ver_Byte2 : 8|8@1+ (1,0) [0|255] ""  PC
 SG_ E2P_Cfg1_SW_Ver_Byte3 : 16|8@1+ (1,0) [0|255] ""  PC
 SG_ E2P_Cfg1_SW_Ver_Byte4 : 24|8@1+ (1,0) [0|255] ""  PC
 SG_ E2P_Cfg1_SW_Ver_Byte5 : 32|8@1+ (1,0) [0|255] ""  PC
 SG_ E2P_Cfg1_SW_Ver_Byte6 : 40|8@1+ (1,0) [0|255] ""  PC
 SG_ E2P_Cfg1_SW_Ver_Byte7 : 48|8@1+ (1,0) [0|255] ""  PC
 SG_ E2P_Cfg1_SW_Ver_Byte8 : 56|8@1+ (1,0) [0|255] ""  PC

BO_ 2483285650 E2P_Cfg1__02: 8 ETH
 SG_ E2P_Cfg1_SW_Ver_Byte1 : 0|8@1+ (1,0) [0|255] ""  PC
 SG_ E2P_Cfg1_SW_Ver_Byte2 : 8|8@1+ (1,0) [0|255] ""  PC
 SG_ E2P_Cfg1_SW_Ver_Byte3 : 16|8@1+ (1,0) [0|255] ""  PC
 SG_ E2P_Cfg1_SW_Ver_Byte4 : 24|8@1+ (1,0) [0|255] ""  PC
 SG_ E2P_Cfg1_SW_Ver_Byte5 : 32|8@1+ (1,0) [0|255] ""  PC
 SG_ E2P_Cfg1_SW_Ver_Byte6 : 40|8@1+ (1,0) [0|255] ""  PC
 SG_ E2P_Cfg1_SW_Ver_Byte7 : 48|8@1+ (1,0) [0|255] ""  PC
 SG_ E2P_Cfg1_SW_Ver_Byte8 : 56|8@1+ (1,0) [0|255] ""  PC

BO_ 2483285651 E2P_Cfg1__03: 8 ETH
 SG_ E2P_Cfg1_SW_Ver_Byte1 : 0|8@1+ (1,0) [0|255] ""  PC
 SG_ E2P_Cfg1_SW_Ver_Byte2 : 8|8@1+ (1,0) [0|255] ""  PC
 SG_ E2P_Cfg1_SW_Ver_Byte3 : 16|8@1+ (1,0) [0|255] ""  PC
 SG_ E2P_Cfg1_SW_Ver_Byte4 : 24|8@1+ (1,0) [0|255] ""  PC
 SG_ E2P_Cfg1_SW_Ver_Byte5 : 32|8@1+ (1,0) [0|255] ""  PC
 SG_ E2P_Cfg1_SW_Ver_Byte6 : 40|8@1+ (1,0) [0|255] ""  PC
 SG_ E2P_Cfg1_SW_Ver_Byte7 : 48|8@1+ (1,0) [0|255] ""  PC
 SG_ E2P_Cfg1_SW_Ver_Byte8 : 56|8@1+ (1,0) [0|255] ""  PC

BO_ 2483285652 E2P_Cfg1__04: 8 ETH
 SG_ E2P_Cfg1_SW_Ver_Byte1 : 0|8@1+ (1,0) [0|255] ""  PC
 SG_ E2P_Cfg1_SW_Ver_Byte2 : 8|8@1+ (1,0) [0|255] ""  PC
 SG_ E2P_Cfg1_SW_Ver_Byte3 : 16|8@1+ (1,0) [0|255] ""  PC
 SG_ E2P_Cfg1_SW_Ver_Byte4 : 24|8@1+ (1,0) [0|255] ""  PC
 SG_ E2P_Cfg1_SW_Ver_Byte5 : 32|8@1+ (1,0) [0|255] ""  PC
 SG_ E2P_Cfg1_SW_Ver_Byte6 : 40|8@1+ (1,0) [0|255] ""  PC
 SG_ E2P_Cfg1_SW_Ver_Byte7 : 48|8@1+ (1,0) [0|255] ""  PC
 SG_ E2P_Cfg1_SW_Ver_Byte8 : 56|8@1+ (1,0) [0|255] ""  PC

BO_ 2483285653 E2P_Cfg1__05: 8 ETH
 SG_ E2P_Cfg1_SW_Ver_Byte1 : 0|8@1+ (1,0) [0|255] ""  PC
 SG_ E2P_Cfg1_SW_Ver_Byte2 : 8|8@1+ (1,0) [0|255] ""  PC
 SG_ E2P_Cfg1_SW_Ver_Byte3 : 16|8@1+ (1,0) [0|255] ""  PC
 SG_ E2P_Cfg1_SW_Ver_Byte4 : 24|8@1+ (1,0) [0|255] ""  PC
 SG_ E2P_Cfg1_SW_Ver_Byte5 : 32|8@1+ (1,0) [0|255] ""  PC
 SG_ E2P_Cfg1_SW_Ver_Byte6 : 40|8@1+ (1,0) [0|255] ""  PC
 SG_ E2P_Cfg1_SW_Ver_Byte7 : 48|8@1+ (1,0) [0|255] ""  PC
 SG_ E2P_Cfg1_SW_Ver_Byte8 : 56|8@1+ (1,0) [0|255] ""  PC

BO_ 2483285654 E2P_Cfg1__06: 8 ETH
 SG_ E2P_Cfg1_SW_Ver_Byte1 : 0|8@1+ (1,0) [0|255] ""  PC
 SG_ E2P_Cfg1_SW_Ver_Byte2 : 8|8@1+ (1,0) [0|255] ""  PC
 SG_ E2P_Cfg1_SW_Ver_Byte3 : 16|8@1+ (1,0) [0|255] ""  PC
 SG_ E2P_Cfg1_SW_Ver_Byte4 : 24|8@1+ (1,0) [0|255] ""  PC
 SG_ E2P_Cfg1_SW_Ver_Byte5 : 32|8@1+ (1,0) [0|255] ""  PC
 SG_ E2P_Cfg1_SW_Ver_Byte6 : 40|8@1+ (1,0) [0|255] ""  PC
 SG_ E2P_Cfg1_SW_Ver_Byte7 : 48|8@1+ (1,0) [0|255] ""  PC
 SG_ E2P_Cfg1_SW_Ver_Byte8 : 56|8@1+ (1,0) [0|255] ""  PC

BO_ 2483285655 E2P_Cfg1__07: 8 ETH
 SG_ E2P_Cfg1_SW_Ver_Byte1 : 0|8@1+ (1,0) [0|255] ""  PC
 SG_ E2P_Cfg1_SW_Ver_Byte2 : 8|8@1+ (1,0) [0|255] ""  PC
 SG_ E2P_Cfg1_SW_Ver_Byte3 : 16|8@1+ (1,0) [0|255] ""  PC
 SG_ E2P_Cfg1_SW_Ver_Byte4 : 24|8@1+ (1,0) [0|255] ""  PC
 SG_ E2P_Cfg1_SW_Ver_Byte5 : 32|8@1+ (1,0) [0|255] ""  PC
 SG_ E2P_Cfg1_SW_Ver_Byte6 : 40|8@1+ (1,0) [0|255] ""  PC
 SG_ E2P_Cfg1_SW_Ver_Byte7 : 48|8@1+ (1,0) [0|255] ""  PC
 SG_ E2P_Cfg1_SW_Ver_Byte8 : 56|8@1+ (1,0) [0|255] ""  PC

BO_ 2483285656 E2P_Cfg1__08: 8 ETH
 SG_ E2P_Cfg1_SW_Ver_Byte1 : 0|8@1+ (1,0) [0|255] ""  PC
 SG_ E2P_Cfg1_SW_Ver_Byte2 : 8|8@1+ (1,0) [0|255] ""  PC
 SG_ E2P_Cfg1_SW_Ver_Byte3 : 16|8@1+ (1,0) [0|255] ""  PC
 SG_ E2P_Cfg1_SW_Ver_Byte4 : 24|8@1+ (1,0) [0|255] ""  PC
 SG_ E2P_Cfg1_SW_Ver_Byte5 : 32|8@1+ (1,0) [0|255] ""  PC
 SG_ E2P_Cfg1_SW_Ver_Byte6 : 40|8@1+ (1,0) [0|255] ""  PC
 SG_ E2P_Cfg1_SW_Ver_Byte7 : 48|8@1+ (1,0) [0|255] ""  PC
 SG_ E2P_Cfg1_SW_Ver_Byte8 : 56|8@1+ (1,0) [0|255] ""  PC

BO_ 2483285657 E2P_Cfg1__09: 8 ETH
 SG_ E2P_Cfg1_SW_Ver_Byte1 : 0|8@1+ (1,0) [0|255] ""  PC
 SG_ E2P_Cfg1_SW_Ver_Byte2 : 8|8@1+ (1,0) [0|255] ""  PC
 SG_ E2P_Cfg1_SW_Ver_Byte3 : 16|8@1+ (1,0) [0|255] ""  PC
 SG_ E2P_Cfg1_SW_Ver_Byte4 : 24|8@1+ (1,0) [0|255] ""  PC
 SG_ E2P_Cfg1_SW_Ver_Byte5 : 32|8@1+ (1,0) [0|255] ""  PC
 SG_ E2P_Cfg1_SW_Ver_Byte6 : 40|8@1+ (1,0) [0|255] ""  PC
 SG_ E2P_Cfg1_SW_Ver_Byte7 : 48|8@1+ (1,0) [0|255] ""  PC
 SG_ E2P_Cfg1_SW_Ver_Byte8 : 56|8@1+ (1,0) [0|255] ""  PC

BO_ 2483285658 E2P_Cfg1__10: 8 ETH
 SG_ E2P_Cfg1_SW_Ver_Byte1 : 0|8@1+ (1,0) [0|255] ""  PC
 SG_ E2P_Cfg1_SW_Ver_Byte2 : 8|8@1+ (1,0) [0|255] ""  PC
 SG_ E2P_Cfg1_SW_Ver_Byte3 : 16|8@1+ (1,0) [0|255] ""  PC
 SG_ E2P_Cfg1_SW_Ver_Byte4 : 24|8@1+ (1,0) [0|255] ""  PC
 SG_ E2P_Cfg1_SW_Ver_Byte5 : 32|8@1+ (1,0) [0|255] ""  PC
 SG_ E2P_Cfg1_SW_Ver_Byte6 : 40|8@1+ (1,0) [0|255] ""  PC
 SG_ E2P_Cfg1_SW_Ver_Byte7 : 48|8@1+ (1,0) [0|255] ""  PC
 SG_ E2P_Cfg1_SW_Ver_Byte8 : 56|8@1+ (1,0) [0|255] ""  PC

BO_ 2483285659 E2P_Cfg1__11: 8 ETH
 SG_ E2P_Cfg1_SW_Ver_Byte1 : 0|8@1+ (1,0) [0|255] ""  PC
 SG_ E2P_Cfg1_SW_Ver_Byte2 : 8|8@1+ (1,0) [0|255] ""  PC
 SG_ E2P_Cfg1_SW_Ver_Byte3 : 16|8@1+ (1,0) [0|255] ""  PC
 SG_ E2P_Cfg1_SW_Ver_Byte4 : 24|8@1+ (1,0) [0|255] ""  PC
 SG_ E2P_Cfg1_SW_Ver_Byte5 : 32|8@1+ (1,0) [0|255] ""  PC
 SG_ E2P_Cfg1_SW_Ver_Byte6 : 40|8@1+ (1,0) [0|255] ""  PC
 SG_ E2P_Cfg1_SW_Ver_Byte7 : 48|8@1+ (1,0) [0|255] ""  PC
 SG_ E2P_Cfg1_SW_Ver_Byte8 : 56|8@1+ (1,0) [0|255] ""  PC

BO_ 2483285660 E2P_Cfg1__12: 8 ETH
 SG_ E2P_Cfg1_SW_Ver_Byte1 : 0|8@1+ (1,0) [0|255] ""  PC
 SG_ E2P_Cfg1_SW_Ver_Byte2 : 8|8@1+ (1,0) [0|255] ""  PC
 SG_ E2P_Cfg1_SW_Ver_Byte3 : 16|8@1+ (1,0) [0|255] ""  PC
 SG_ E2P_Cfg1_SW_Ver_Byte4 : 24|8@1+ (1,0) [0|255] ""  PC
 SG_ E2P_Cfg1_SW_Ver_Byte5 : 32|8@1+ (1,0) [0|255] ""  PC
 SG_ E2P_Cfg1_SW_Ver_Byte6 : 40|8@1+ (1,0) [0|255] ""  PC
 SG_ E2P_Cfg1_SW_Ver_Byte7 : 48|8@1+ (1,0) [0|255] ""  PC
 SG_ E2P_Cfg1_SW_Ver_Byte8 : 56|8@1+ (1,0) [0|255] ""  PC

BO_ 2483285661 E2P_Cfg1__13: 8 ETH
 SG_ E2P_Cfg1_SW_Ver_Byte1 : 0|8@1+ (1,0) [0|255] ""  PC
 SG_ E2P_Cfg1_SW_Ver_Byte2 : 8|8@1+ (1,0) [0|255] ""  PC
 SG_ E2P_Cfg1_SW_Ver_Byte3 : 16|8@1+ (1,0) [0|255] ""  PC
 SG_ E2P_Cfg1_SW_Ver_Byte4 : 24|8@1+ (1,0) [0|255] ""  PC
 SG_ E2P_Cfg1_SW_Ver_Byte5 : 32|8@1+ (1,0) [0|255] ""  PC
 SG_ E2P_Cfg1_SW_Ver_Byte6 : 40|8@1+ (1,0) [0|255] ""  PC
 SG_ E2P_Cfg1_SW_Ver_Byte7 : 48|8@1+ (1,0) [0|255] ""  PC
 SG_ E2P_Cfg1_SW_Ver_Byte8 : 56|8@1+ (1,0) [0|255] ""  PC

BO_ 2483285662 E2P_Cfg1__14: 8 ETH
 SG_ E2P_Cfg1_SW_Ver_Byte1 : 0|8@1+ (1,0) [0|255] ""  PC
 SG_ E2P_Cfg1_SW_Ver_Byte2 : 8|8@1+ (1,0) [0|255] ""  PC
 SG_ E2P_Cfg1_SW_Ver_Byte3 : 16|8@1+ (1,0) [0|255] ""  PC
 SG_ E2P_Cfg1_SW_Ver_Byte4 : 24|8@1+ (1,0) [0|255] ""  PC
 SG_ E2P_Cfg1_SW_Ver_Byte5 : 32|8@1+ (1,0) [0|255] ""  PC
 SG_ E2P_Cfg1_SW_Ver_Byte6 : 40|8@1+ (1,0) [0|255] ""  PC
 SG_ E2P_Cfg1_SW_Ver_Byte7 : 48|8@1+ (1,0) [0|255] ""  PC
 SG_ E2P_Cfg1_SW_Ver_Byte8 : 56|8@1+ (1,0) [0|255] ""  PC

BO_ 2483285663 E2P_Cfg1__15: 8 ETH
 SG_ E2P_Cfg1_SW_Ver_Byte1 : 0|8@1+ (1,0) [0|255] ""  PC
 SG_ E2P_Cfg1_SW_Ver_Byte2 : 8|8@1+ (1,0) [0|255] ""  PC
 SG_ E2P_Cfg1_SW_Ver_Byte3 : 16|8@1+ (1,0) [0|255] ""  PC
 SG_ E2P_Cfg1_SW_Ver_Byte4 : 24|8@1+ (1,0) [0|255] ""  PC
 SG_ E2P_Cfg1_SW_Ver_Byte5 : 32|8@1+ (1,0) [0|255] ""  PC
 SG_ E2P_Cfg1_SW_Ver_Byte6 : 40|8@1+ (1,0) [0|255] ""  PC
 SG_ E2P_Cfg1_SW_Ver_Byte7 : 48|8@1+ (1,0) [0|255] ""  PC
 SG_ E2P_Cfg1_SW_Ver_Byte8 : 56|8@1+ (1,0) [0|255] ""  PC

BO_ 2483285664 E2P_Cfg1__16: 8 ETH
 SG_ E2P_Cfg1_SW_Ver_Byte1 : 0|8@1+ (1,0) [0|255] ""  PC
 SG_ E2P_Cfg1_SW_Ver_Byte2 : 8|8@1+ (1,0) [0|255] ""  PC
 SG_ E2P_Cfg1_SW_Ver_Byte3 : 16|8@1+ (1,0) [0|255] ""  PC
 SG_ E2P_Cfg1_SW_Ver_Byte4 : 24|8@1+ (1,0) [0|255] ""  PC
 SG_ E2P_Cfg1_SW_Ver_Byte5 : 32|8@1+ (1,0) [0|255] ""  PC
 SG_ E2P_Cfg1_SW_Ver_Byte6 : 40|8@1+ (1,0) [0|255] ""  PC
 SG_ E2P_Cfg1_SW_Ver_Byte7 : 48|8@1+ (1,0) [0|255] ""  PC
 SG_ E2P_Cfg1_SW_Ver_Byte8 : 56|8@1+ (1,0) [0|255] ""  PC

BO_ 2483285665 E2P_Cfg1__17: 8 ETH
 SG_ E2P_Cfg1_SW_Ver_Byte1 : 0|8@1+ (1,0) [0|255] ""  PC
 SG_ E2P_Cfg1_SW_Ver_Byte2 : 8|8@1+ (1,0) [0|255] ""  PC
 SG_ E2P_Cfg1_SW_Ver_Byte3 : 16|8@1+ (1,0) [0|255] ""  PC
 SG_ E2P_Cfg1_SW_Ver_Byte4 : 24|8@1+ (1,0) [0|255] ""  PC
 SG_ E2P_Cfg1_SW_Ver_Byte5 : 32|8@1+ (1,0) [0|255] ""  PC
 SG_ E2P_Cfg1_SW_Ver_Byte6 : 40|8@1+ (1,0) [0|255] ""  PC
 SG_ E2P_Cfg1_SW_Ver_Byte7 : 48|8@1+ (1,0) [0|255] ""  PC
 SG_ E2P_Cfg1_SW_Ver_Byte8 : 56|8@1+ (1,0) [0|255] ""  PC

BO_ 2483285666 E2P_Cfg1__18: 8 ETH
 SG_ E2P_Cfg1_SW_Ver_Byte1 : 0|8@1+ (1,0) [0|255] ""  PC
 SG_ E2P_Cfg1_SW_Ver_Byte2 : 8|8@1+ (1,0) [0|255] ""  PC
 SG_ E2P_Cfg1_SW_Ver_Byte3 : 16|8@1+ (1,0) [0|255] ""  PC
 SG_ E2P_Cfg1_SW_Ver_Byte4 : 24|8@1+ (1,0) [0|255] ""  PC
 SG_ E2P_Cfg1_SW_Ver_Byte5 : 32|8@1+ (1,0) [0|255] ""  PC
 SG_ E2P_Cfg1_SW_Ver_Byte6 : 40|8@1+ (1,0) [0|255] ""  PC
 SG_ E2P_Cfg1_SW_Ver_Byte7 : 48|8@1+ (1,0) [0|255] ""  PC
 SG_ E2P_Cfg1_SW_Ver_Byte8 : 56|8@1+ (1,0) [0|255] ""  PC

BO_ 2483285667 E2P_Cfg1__19: 8 ETH
 SG_ E2P_Cfg1_SW_Ver_Byte1 : 0|8@1+ (1,0) [0|255] ""  PC
 SG_ E2P_Cfg1_SW_Ver_Byte2 : 8|8@1+ (1,0) [0|255] ""  PC
 SG_ E2P_Cfg1_SW_Ver_Byte3 : 16|8@1+ (1,0) [0|255] ""  PC
 SG_ E2P_Cfg1_SW_Ver_Byte4 : 24|8@1+ (1,0) [0|255] ""  PC
 SG_ E2P_Cfg1_SW_Ver_Byte5 : 32|8@1+ (1,0) [0|255] ""  PC
 SG_ E2P_Cfg1_SW_Ver_Byte6 : 40|8@1+ (1,0) [0|255] ""  PC
 SG_ E2P_Cfg1_SW_Ver_Byte7 : 48|8@1+ (1,0) [0|255] ""  PC
 SG_ E2P_Cfg1_SW_Ver_Byte8 : 56|8@1+ (1,0) [0|255] ""  PC

BO_ 2483285668 E2P_Cfg1__20: 8 ETH
 SG_ E2P_Cfg1_SW_Ver_Byte1 : 0|8@1+ (1,0) [0|255] ""  PC
 SG_ E2P_Cfg1_SW_Ver_Byte2 : 8|8@1+ (1,0) [0|255] ""  PC
 SG_ E2P_Cfg1_SW_Ver_Byte3 : 16|8@1+ (1,0) [0|255] ""  PC
 SG_ E2P_Cfg1_SW_Ver_Byte4 : 24|8@1+ (1,0) [0|255] ""  PC
 SG_ E2P_Cfg1_SW_Ver_Byte5 : 32|8@1+ (1,0) [0|255] ""  PC
 SG_ E2P_Cfg1_SW_Ver_Byte6 : 40|8@1+ (1,0) [0|255] ""  PC
 SG_ E2P_Cfg1_SW_Ver_Byte7 : 48|8@1+ (1,0) [0|255] ""  PC
 SG_ E2P_Cfg1_SW_Ver_Byte8 : 56|8@1+ (1,0) [0|255] ""  PC

BO_ 2483285669 E2P_Cfg1__21: 8 ETH
 SG_ E2P_Cfg1_SW_Ver_Byte1 : 0|8@1+ (1,0) [0|255] ""  PC
 SG_ E2P_Cfg1_SW_Ver_Byte2 : 8|8@1+ (1,0) [0|255] ""  PC
 SG_ E2P_Cfg1_SW_Ver_Byte3 : 16|8@1+ (1,0) [0|255] ""  PC
 SG_ E2P_Cfg1_SW_Ver_Byte4 : 24|8@1+ (1,0) [0|255] ""  PC
 SG_ E2P_Cfg1_SW_Ver_Byte5 : 32|8@1+ (1,0) [0|255] ""  PC
 SG_ E2P_Cfg1_SW_Ver_Byte6 : 40|8@1+ (1,0) [0|255] ""  PC
 SG_ E2P_Cfg1_SW_Ver_Byte7 : 48|8@1+ (1,0) [0|255] ""  PC
 SG_ E2P_Cfg1_SW_Ver_Byte8 : 56|8@1+ (1,0) [0|255] ""  PC

BO_ 2483285670 E2P_Cfg1__22: 8 ETH
 SG_ E2P_Cfg1_SW_Ver_Byte1 : 0|8@1+ (1,0) [0|255] ""  PC
 SG_ E2P_Cfg1_SW_Ver_Byte2 : 8|8@1+ (1,0) [0|255] ""  PC
 SG_ E2P_Cfg1_SW_Ver_Byte3 : 16|8@1+ (1,0) [0|255] ""  PC
 SG_ E2P_Cfg1_SW_Ver_Byte4 : 24|8@1+ (1,0) [0|255] ""  PC
 SG_ E2P_Cfg1_SW_Ver_Byte5 : 32|8@1+ (1,0) [0|255] ""  PC
 SG_ E2P_Cfg1_SW_Ver_Byte6 : 40|8@1+ (1,0) [0|255] ""  PC
 SG_ E2P_Cfg1_SW_Ver_Byte7 : 48|8@1+ (1,0) [0|255] ""  PC
 SG_ E2P_Cfg1_SW_Ver_Byte8 : 56|8@1+ (1,0) [0|255] ""  PC

BO_ 2483285671 E2P_Cfg1__23: 8 ETH
 SG_ E2P_Cfg1_SW_Ver_Byte1 : 0|8@1+ (1,0) [0|255] ""  PC
 SG_ E2P_Cfg1_SW_Ver_Byte2 : 8|8@1+ (1,0) [0|255] ""  PC
 SG_ E2P_Cfg1_SW_Ver_Byte3 : 16|8@1+ (1,0) [0|255] ""  PC
 SG_ E2P_Cfg1_SW_Ver_Byte4 : 24|8@1+ (1,0) [0|255] ""  PC
 SG_ E2P_Cfg1_SW_Ver_Byte5 : 32|8@1+ (1,0) [0|255] ""  PC
 SG_ E2P_Cfg1_SW_Ver_Byte6 : 40|8@1+ (1,0) [0|255] ""  PC
 SG_ E2P_Cfg1_SW_Ver_Byte7 : 48|8@1+ (1,0) [0|255] ""  PC
 SG_ E2P_Cfg1_SW_Ver_Byte8 : 56|8@1+ (1,0) [0|255] ""  PC

BO_ 2483285672 E2P_Cfg1__24: 8 ETH
 SG_ E2P_Cfg1_SW_Ver_Byte1 : 0|8@1+ (1,0) [0|255] ""  PC
 SG_ E2P_Cfg1_SW_Ver_Byte2 : 8|8@1+ (1,0) [0|255] ""  PC
 SG_ E2P_Cfg1_SW_Ver_Byte3 : 16|8@1+ (1,0) [0|255] ""  PC
 SG_ E2P_Cfg1_SW_Ver_Byte4 : 24|8@1+ (1,0) [0|255] ""  PC
 SG_ E2P_Cfg1_SW_Ver_Byte5 : 32|8@1+ (1,0) [0|255] ""  PC
 SG_ E2P_Cfg1_SW_Ver_Byte6 : 40|8@1+ (1,0) [0|255] ""  PC
 SG_ E2P_Cfg1_SW_Ver_Byte7 : 48|8@1+ (1,0) [0|255] ""  PC
 SG_ E2P_Cfg1_SW_Ver_Byte8 : 56|8@1+ (1,0) [0|255] ""  PC

BO_ 2483285673 E2P_Cfg1__25: 8 ETH
 SG_ E2P_Cfg1_SW_Ver_Byte1 : 0|8@1+ (1,0) [0|255] ""  PC
 SG_ E2P_Cfg1_SW_Ver_Byte2 : 8|8@1+ (1,0) [0|255] ""  PC
 SG_ E2P_Cfg1_SW_Ver_Byte3 : 16|8@1+ (1,0) [0|255] ""  PC
 SG_ E2P_Cfg1_SW_Ver_Byte4 : 24|8@1+ (1,0) [0|255] ""  PC
 SG_ E2P_Cfg1_SW_Ver_Byte5 : 32|8@1+ (1,0) [0|255] ""  PC
 SG_ E2P_Cfg1_SW_Ver_Byte6 : 40|8@1+ (1,0) [0|255] ""  PC
 SG_ E2P_Cfg1_SW_Ver_Byte7 : 48|8@1+ (1,0) [0|255] ""  PC
 SG_ E2P_Cfg1_SW_Ver_Byte8 : 56|8@1+ (1,0) [0|255] ""  PC

BO_ 2483285674 E2P_Cfg1__26: 8 ETH
 SG_ E2P_Cfg1_SW_Ver_Byte1 : 0|8@1+ (1,0) [0|255] ""  PC
 SG_ E2P_Cfg1_SW_Ver_Byte2 : 8|8@1+ (1,0) [0|255] ""  PC
 SG_ E2P_Cfg1_SW_Ver_Byte3 : 16|8@1+ (1,0) [0|255] ""  PC
 SG_ E2P_Cfg1_SW_Ver_Byte4 : 24|8@1+ (1,0) [0|255] ""  PC
 SG_ E2P_Cfg1_SW_Ver_Byte5 : 32|8@1+ (1,0) [0|255] ""  PC
 SG_ E2P_Cfg1_SW_Ver_Byte6 : 40|8@1+ (1,0) [0|255] ""  PC
 SG_ E2P_Cfg1_SW_Ver_Byte7 : 48|8@1+ (1,0) [0|255] ""  PC
 SG_ E2P_Cfg1_SW_Ver_Byte8 : 56|8@1+ (1,0) [0|255] ""  PC

BO_ 2483285675 E2P_Cfg1__27: 8 ETH
 SG_ E2P_Cfg1_SW_Ver_Byte1 : 0|8@1+ (1,0) [0|255] ""  PC
 SG_ E2P_Cfg1_SW_Ver_Byte2 : 8|8@1+ (1,0) [0|255] ""  PC
 SG_ E2P_Cfg1_SW_Ver_Byte3 : 16|8@1+ (1,0) [0|255] ""  PC
 SG_ E2P_Cfg1_SW_Ver_Byte4 : 24|8@1+ (1,0) [0|255] ""  PC
 SG_ E2P_Cfg1_SW_Ver_Byte5 : 32|8@1+ (1,0) [0|255] ""  PC
 SG_ E2P_Cfg1_SW_Ver_Byte6 : 40|8@1+ (1,0) [0|255] ""  PC
 SG_ E2P_Cfg1_SW_Ver_Byte7 : 48|8@1+ (1,0) [0|255] ""  PC
 SG_ E2P_Cfg1_SW_Ver_Byte8 : 56|8@1+ (1,0) [0|255] ""  PC

BO_ 2483285676 E2P_Cfg1__28: 8 ETH
 SG_ E2P_Cfg1_SW_Ver_Byte1 : 0|8@1+ (1,0) [0|255] ""  PC
 SG_ E2P_Cfg1_SW_Ver_Byte2 : 8|8@1+ (1,0) [0|255] ""  PC
 SG_ E2P_Cfg1_SW_Ver_Byte3 : 16|8@1+ (1,0) [0|255] ""  PC
 SG_ E2P_Cfg1_SW_Ver_Byte4 : 24|8@1+ (1,0) [0|255] ""  PC
 SG_ E2P_Cfg1_SW_Ver_Byte5 : 32|8@1+ (1,0) [0|255] ""  PC
 SG_ E2P_Cfg1_SW_Ver_Byte6 : 40|8@1+ (1,0) [0|255] ""  PC
 SG_ E2P_Cfg1_SW_Ver_Byte7 : 48|8@1+ (1,0) [0|255] ""  PC
 SG_ E2P_Cfg1_SW_Ver_Byte8 : 56|8@1+ (1,0) [0|255] ""  PC

BO_ 2483285677 E2P_Cfg1__29: 8 ETH
 SG_ E2P_Cfg1_SW_Ver_Byte1 : 0|8@1+ (1,0) [0|255] ""  PC
 SG_ E2P_Cfg1_SW_Ver_Byte2 : 8|8@1+ (1,0) [0|255] ""  PC
 SG_ E2P_Cfg1_SW_Ver_Byte3 : 16|8@1+ (1,0) [0|255] ""  PC
 SG_ E2P_Cfg1_SW_Ver_Byte4 : 24|8@1+ (1,0) [0|255] ""  PC
 SG_ E2P_Cfg1_SW_Ver_Byte5 : 32|8@1+ (1,0) [0|255] ""  PC
 SG_ E2P_Cfg1_SW_Ver_Byte6 : 40|8@1+ (1,0) [0|255] ""  PC
 SG_ E2P_Cfg1_SW_Ver_Byte7 : 48|8@1+ (1,0) [0|255] ""  PC
 SG_ E2P_Cfg1_SW_Ver_Byte8 : 56|8@1+ (1,0) [0|255] ""  PC

BO_ 2483285678 E2P_Cfg1__30: 8 ETH
 SG_ E2P_Cfg1_SW_Ver_Byte1 : 0|8@1+ (1,0) [0|255] ""  PC
 SG_ E2P_Cfg1_SW_Ver_Byte2 : 8|8@1+ (1,0) [0|255] ""  PC
 SG_ E2P_Cfg1_SW_Ver_Byte3 : 16|8@1+ (1,0) [0|255] ""  PC
 SG_ E2P_Cfg1_SW_Ver_Byte4 : 24|8@1+ (1,0) [0|255] ""  PC
 SG_ E2P_Cfg1_SW_Ver_Byte5 : 32|8@1+ (1,0) [0|255] ""  PC
 SG_ E2P_Cfg1_SW_Ver_Byte6 : 40|8@1+ (1,0) [0|255] ""  PC
 SG_ E2P_Cfg1_SW_Ver_Byte7 : 48|8@1+ (1,0) [0|255] ""  PC
 SG_ E2P_Cfg1_SW_Ver_Byte8 : 56|8@1+ (1,0) [0|255] ""  PC

BO_ 2483285679 E2P_Cfg1__31: 8 ETH
 SG_ E2P_Cfg1_SW_Ver_Byte1 : 0|8@1+ (1,0) [0|255] ""  PC
 SG_ E2P_Cfg1_SW_Ver_Byte2 : 8|8@1+ (1,0) [0|255] ""  PC
 SG_ E2P_Cfg1_SW_Ver_Byte3 : 16|8@1+ (1,0) [0|255] ""  PC
 SG_ E2P_Cfg1_SW_Ver_Byte4 : 24|8@1+ (1,0) [0|255] ""  PC
 SG_ E2P_Cfg1_SW_Ver_Byte5 : 32|8@1+ (1,0) [0|255] ""  PC
 SG_ E2P_Cfg1_SW_Ver_Byte6 : 40|8@1+ (1,0) [0|255] ""  PC
 SG_ E2P_Cfg1_SW_Ver_Byte7 : 48|8@1+ (1,0) [0|255] ""  PC
 SG_ E2P_Cfg1_SW_Ver_Byte8 : 56|8@1+ (1,0) [0|255] ""  PC

BO_ 2483351185 E2P_Cfg2__01: 8 ETH
 SG_ E2P_Cfg2_SW_Ver_Byte9 : 0|8@1+ (1,0) [0|255] ""  PC
 SG_ E2P_Cfg2_SW_Ver_Byte10 : 8|8@1+ (1,0) [0|255] ""  PC
 SG_ E2P_Cfg2_SW_Ver_Byte11 : 16|8@1+ (1,0) [0|255] ""  PC
 SG_ E2P_Cfg2_SW_Ver_Byte12 : 24|8@1+ (1,0) [0|255] ""  PC
 SG_ E2P_Cfg2_SW_Ver_Byte13 : 32|8@1+ (1,0) [0|255] ""  PC
 SG_ E2P_Cfg2_SW_Ver_Byte14 : 40|8@1+ (1,0) [0|255] ""  PC
 SG_ E2P_Cfg2_SW_Ver_Byte15 : 48|8@1+ (1,0) [0|255] ""  PC
 SG_ E2P_Cfg2_SW_Ver_Byte16 : 56|8@1+ (1,0) [0|255] ""  PC

BO_ 2483351186 E2P_Cfg2__02: 8 ETH
 SG_ E2P_Cfg2_SW_Ver_Byte9 : 0|8@1+ (1,0) [0|255] ""  PC
 SG_ E2P_Cfg2_SW_Ver_Byte10 : 8|8@1+ (1,0) [0|255] ""  PC
 SG_ E2P_Cfg2_SW_Ver_Byte11 : 16|8@1+ (1,0) [0|255] ""  PC
 SG_ E2P_Cfg2_SW_Ver_Byte12 : 24|8@1+ (1,0) [0|255] ""  PC
 SG_ E2P_Cfg2_SW_Ver_Byte13 : 32|8@1+ (1,0) [0|255] ""  PC
 SG_ E2P_Cfg2_SW_Ver_Byte14 : 40|8@1+ (1,0) [0|255] ""  PC
 SG_ E2P_Cfg2_SW_Ver_Byte15 : 48|8@1+ (1,0) [0|255] ""  PC
 SG_ E2P_Cfg2_SW_Ver_Byte16 : 56|8@1+ (1,0) [0|255] ""  PC

BO_ 2483351187 E2P_Cfg2__03: 8 ETH
 SG_ E2P_Cfg2_SW_Ver_Byte9 : 0|8@1+ (1,0) [0|255] ""  PC
 SG_ E2P_Cfg2_SW_Ver_Byte10 : 8|8@1+ (1,0) [0|255] ""  PC
 SG_ E2P_Cfg2_SW_Ver_Byte11 : 16|8@1+ (1,0) [0|255] ""  PC
 SG_ E2P_Cfg2_SW_Ver_Byte12 : 24|8@1+ (1,0) [0|255] ""  PC
 SG_ E2P_Cfg2_SW_Ver_Byte13 : 32|8@1+ (1,0) [0|255] ""  PC
 SG_ E2P_Cfg2_SW_Ver_Byte14 : 40|8@1+ (1,0) [0|255] ""  PC
 SG_ E2P_Cfg2_SW_Ver_Byte15 : 48|8@1+ (1,0) [0|255] ""  PC
 SG_ E2P_Cfg2_SW_Ver_Byte16 : 56|8@1+ (1,0) [0|255] ""  PC

BO_ 2483351188 E2P_Cfg2__04: 8 ETH
 SG_ E2P_Cfg2_SW_Ver_Byte9 : 0|8@1+ (1,0) [0|255] ""  PC
 SG_ E2P_Cfg2_SW_Ver_Byte10 : 8|8@1+ (1,0) [0|255] ""  PC
 SG_ E2P_Cfg2_SW_Ver_Byte11 : 16|8@1+ (1,0) [0|255] ""  PC
 SG_ E2P_Cfg2_SW_Ver_Byte12 : 24|8@1+ (1,0) [0|255] ""  PC
 SG_ E2P_Cfg2_SW_Ver_Byte13 : 32|8@1+ (1,0) [0|255] ""  PC
 SG_ E2P_Cfg2_SW_Ver_Byte14 : 40|8@1+ (1,0) [0|255] ""  PC
 SG_ E2P_Cfg2_SW_Ver_Byte15 : 48|8@1+ (1,0) [0|255] ""  PC
 SG_ E2P_Cfg2_SW_Ver_Byte16 : 56|8@1+ (1,0) [0|255] ""  PC

BO_ 2483351189 E2P_Cfg2__05: 8 ETH
 SG_ E2P_Cfg2_SW_Ver_Byte9 : 0|8@1+ (1,0) [0|255] ""  PC
 SG_ E2P_Cfg2_SW_Ver_Byte10 : 8|8@1+ (1,0) [0|255] ""  PC
 SG_ E2P_Cfg2_SW_Ver_Byte11 : 16|8@1+ (1,0) [0|255] ""  PC
 SG_ E2P_Cfg2_SW_Ver_Byte12 : 24|8@1+ (1,0) [0|255] ""  PC
 SG_ E2P_Cfg2_SW_Ver_Byte13 : 32|8@1+ (1,0) [0|255] ""  PC
 SG_ E2P_Cfg2_SW_Ver_Byte14 : 40|8@1+ (1,0) [0|255] ""  PC
 SG_ E2P_Cfg2_SW_Ver_Byte15 : 48|8@1+ (1,0) [0|255] ""  PC
 SG_ E2P_Cfg2_SW_Ver_Byte16 : 56|8@1+ (1,0) [0|255] ""  PC

BO_ 2483351190 E2P_Cfg2__06: 8 ETH
 SG_ E2P_Cfg2_SW_Ver_Byte9 : 0|8@1+ (1,0) [0|255] ""  PC
 SG_ E2P_Cfg2_SW_Ver_Byte10 : 8|8@1+ (1,0) [0|255] ""  PC
 SG_ E2P_Cfg2_SW_Ver_Byte11 : 16|8@1+ (1,0) [0|255] ""  PC
 SG_ E2P_Cfg2_SW_Ver_Byte12 : 24|8@1+ (1,0) [0|255] ""  PC
 SG_ E2P_Cfg2_SW_Ver_Byte13 : 32|8@1+ (1,0) [0|255] ""  PC
 SG_ E2P_Cfg2_SW_Ver_Byte14 : 40|8@1+ (1,0) [0|255] ""  PC
 SG_ E2P_Cfg2_SW_Ver_Byte15 : 48|8@1+ (1,0) [0|255] ""  PC
 SG_ E2P_Cfg2_SW_Ver_Byte16 : 56|8@1+ (1,0) [0|255] ""  PC

BO_ 2483351191 E2P_Cfg2__07: 8 ETH
 SG_ E2P_Cfg2_SW_Ver_Byte9 : 0|8@1+ (1,0) [0|255] ""  PC
 SG_ E2P_Cfg2_SW_Ver_Byte10 : 8|8@1+ (1,0) [0|255] ""  PC
 SG_ E2P_Cfg2_SW_Ver_Byte11 : 16|8@1+ (1,0) [0|255] ""  PC
 SG_ E2P_Cfg2_SW_Ver_Byte12 : 24|8@1+ (1,0) [0|255] ""  PC
 SG_ E2P_Cfg2_SW_Ver_Byte13 : 32|8@1+ (1,0) [0|255] ""  PC
 SG_ E2P_Cfg2_SW_Ver_Byte14 : 40|8@1+ (1,0) [0|255] ""  PC
 SG_ E2P_Cfg2_SW_Ver_Byte15 : 48|8@1+ (1,0) [0|255] ""  PC
 SG_ E2P_Cfg2_SW_Ver_Byte16 : 56|8@1+ (1,0) [0|255] ""  PC

BO_ 2483351192 E2P_Cfg2__08: 8 ETH
 SG_ E2P_Cfg2_SW_Ver_Byte9 : 0|8@1+ (1,0) [0|255] ""  PC
 SG_ E2P_Cfg2_SW_Ver_Byte10 : 8|8@1+ (1,0) [0|255] ""  PC
 SG_ E2P_Cfg2_SW_Ver_Byte11 : 16|8@1+ (1,0) [0|255] ""  PC
 SG_ E2P_Cfg2_SW_Ver_Byte12 : 24|8@1+ (1,0) [0|255] ""  PC
 SG_ E2P_Cfg2_SW_Ver_Byte13 : 32|8@1+ (1,0) [0|255] ""  PC
 SG_ E2P_Cfg2_SW_Ver_Byte14 : 40|8@1+ (1,0) [0|255] ""  PC
 SG_ E2P_Cfg2_SW_Ver_Byte15 : 48|8@1+ (1,0) [0|255] ""  PC
 SG_ E2P_Cfg2_SW_Ver_Byte16 : 56|8@1+ (1,0) [0|255] ""  PC

BO_ 2483351193 E2P_Cfg2__09: 8 ETH
 SG_ E2P_Cfg2_SW_Ver_Byte9 : 0|8@1+ (1,0) [0|255] ""  PC
 SG_ E2P_Cfg2_SW_Ver_Byte10 : 8|8@1+ (1,0) [0|255] ""  PC
 SG_ E2P_Cfg2_SW_Ver_Byte11 : 16|8@1+ (1,0) [0|255] ""  PC
 SG_ E2P_Cfg2_SW_Ver_Byte12 : 24|8@1+ (1,0) [0|255] ""  PC
 SG_ E2P_Cfg2_SW_Ver_Byte13 : 32|8@1+ (1,0) [0|255] ""  PC
 SG_ E2P_Cfg2_SW_Ver_Byte14 : 40|8@1+ (1,0) [0|255] ""  PC
 SG_ E2P_Cfg2_SW_Ver_Byte15 : 48|8@1+ (1,0) [0|255] ""  PC
 SG_ E2P_Cfg2_SW_Ver_Byte16 : 56|8@1+ (1,0) [0|255] ""  PC

BO_ 2483351194 E2P_Cfg2__10: 8 ETH
 SG_ E2P_Cfg2_SW_Ver_Byte9 : 0|8@1+ (1,0) [0|255] ""  PC
 SG_ E2P_Cfg2_SW_Ver_Byte10 : 8|8@1+ (1,0) [0|255] ""  PC
 SG_ E2P_Cfg2_SW_Ver_Byte11 : 16|8@1+ (1,0) [0|255] ""  PC
 SG_ E2P_Cfg2_SW_Ver_Byte12 : 24|8@1+ (1,0) [0|255] ""  PC
 SG_ E2P_Cfg2_SW_Ver_Byte13 : 32|8@1+ (1,0) [0|255] ""  PC
 SG_ E2P_Cfg2_SW_Ver_Byte14 : 40|8@1+ (1,0) [0|255] ""  PC
 SG_ E2P_Cfg2_SW_Ver_Byte15 : 48|8@1+ (1,0) [0|255] ""  PC
 SG_ E2P_Cfg2_SW_Ver_Byte16 : 56|8@1+ (1,0) [0|255] ""  PC

BO_ 2483351195 E2P_Cfg2__11: 8 ETH
 SG_ E2P_Cfg2_SW_Ver_Byte9 : 0|8@1+ (1,0) [0|255] ""  PC
 SG_ E2P_Cfg2_SW_Ver_Byte10 : 8|8@1+ (1,0) [0|255] ""  PC
 SG_ E2P_Cfg2_SW_Ver_Byte11 : 16|8@1+ (1,0) [0|255] ""  PC
 SG_ E2P_Cfg2_SW_Ver_Byte12 : 24|8@1+ (1,0) [0|255] ""  PC
 SG_ E2P_Cfg2_SW_Ver_Byte13 : 32|8@1+ (1,0) [0|255] ""  PC
 SG_ E2P_Cfg2_SW_Ver_Byte14 : 40|8@1+ (1,0) [0|255] ""  PC
 SG_ E2P_Cfg2_SW_Ver_Byte15 : 48|8@1+ (1,0) [0|255] ""  PC
 SG_ E2P_Cfg2_SW_Ver_Byte16 : 56|8@1+ (1,0) [0|255] ""  PC

BO_ 2483351196 E2P_Cfg2__12: 8 ETH
 SG_ E2P_Cfg2_SW_Ver_Byte9 : 0|8@1+ (1,0) [0|255] ""  PC
 SG_ E2P_Cfg2_SW_Ver_Byte10 : 8|8@1+ (1,0) [0|255] ""  PC
 SG_ E2P_Cfg2_SW_Ver_Byte11 : 16|8@1+ (1,0) [0|255] ""  PC
 SG_ E2P_Cfg2_SW_Ver_Byte12 : 24|8@1+ (1,0) [0|255] ""  PC
 SG_ E2P_Cfg2_SW_Ver_Byte13 : 32|8@1+ (1,0) [0|255] ""  PC
 SG_ E2P_Cfg2_SW_Ver_Byte14 : 40|8@1+ (1,0) [0|255] ""  PC
 SG_ E2P_Cfg2_SW_Ver_Byte15 : 48|8@1+ (1,0) [0|255] ""  PC
 SG_ E2P_Cfg2_SW_Ver_Byte16 : 56|8@1+ (1,0) [0|255] ""  PC

BO_ 2483351197 E2P_Cfg2__13: 8 ETH
 SG_ E2P_Cfg2_SW_Ver_Byte9 : 0|8@1+ (1,0) [0|255] ""  PC
 SG_ E2P_Cfg2_SW_Ver_Byte10 : 8|8@1+ (1,0) [0|255] ""  PC
 SG_ E2P_Cfg2_SW_Ver_Byte11 : 16|8@1+ (1,0) [0|255] ""  PC
 SG_ E2P_Cfg2_SW_Ver_Byte12 : 24|8@1+ (1,0) [0|255] ""  PC
 SG_ E2P_Cfg2_SW_Ver_Byte13 : 32|8@1+ (1,0) [0|255] ""  PC
 SG_ E2P_Cfg2_SW_Ver_Byte14 : 40|8@1+ (1,0) [0|255] ""  PC
 SG_ E2P_Cfg2_SW_Ver_Byte15 : 48|8@1+ (1,0) [0|255] ""  PC
 SG_ E2P_Cfg2_SW_Ver_Byte16 : 56|8@1+ (1,0) [0|255] ""  PC

BO_ 2483351198 E2P_Cfg2__14: 8 ETH
 SG_ E2P_Cfg2_SW_Ver_Byte9 : 0|8@1+ (1,0) [0|255] ""  PC
 SG_ E2P_Cfg2_SW_Ver_Byte10 : 8|8@1+ (1,0) [0|255] ""  PC
 SG_ E2P_Cfg2_SW_Ver_Byte11 : 16|8@1+ (1,0) [0|255] ""  PC
 SG_ E2P_Cfg2_SW_Ver_Byte12 : 24|8@1+ (1,0) [0|255] ""  PC
 SG_ E2P_Cfg2_SW_Ver_Byte13 : 32|8@1+ (1,0) [0|255] ""  PC
 SG_ E2P_Cfg2_SW_Ver_Byte14 : 40|8@1+ (1,0) [0|255] ""  PC
 SG_ E2P_Cfg2_SW_Ver_Byte15 : 48|8@1+ (1,0) [0|255] ""  PC
 SG_ E2P_Cfg2_SW_Ver_Byte16 : 56|8@1+ (1,0) [0|255] ""  PC

BO_ 2483351199 E2P_Cfg2__15: 8 ETH
 SG_ E2P_Cfg2_SW_Ver_Byte9 : 0|8@1+ (1,0) [0|255] ""  PC
 SG_ E2P_Cfg2_SW_Ver_Byte10 : 8|8@1+ (1,0) [0|255] ""  PC
 SG_ E2P_Cfg2_SW_Ver_Byte11 : 16|8@1+ (1,0) [0|255] ""  PC
 SG_ E2P_Cfg2_SW_Ver_Byte12 : 24|8@1+ (1,0) [0|255] ""  PC
 SG_ E2P_Cfg2_SW_Ver_Byte13 : 32|8@1+ (1,0) [0|255] ""  PC
 SG_ E2P_Cfg2_SW_Ver_Byte14 : 40|8@1+ (1,0) [0|255] ""  PC
 SG_ E2P_Cfg2_SW_Ver_Byte15 : 48|8@1+ (1,0) [0|255] ""  PC
 SG_ E2P_Cfg2_SW_Ver_Byte16 : 56|8@1+ (1,0) [0|255] ""  PC

BO_ 2483351200 E2P_Cfg2__16: 8 ETH
 SG_ E2P_Cfg2_SW_Ver_Byte9 : 0|8@1+ (1,0) [0|255] ""  PC
 SG_ E2P_Cfg2_SW_Ver_Byte10 : 8|8@1+ (1,0) [0|255] ""  PC
 SG_ E2P_Cfg2_SW_Ver_Byte11 : 16|8@1+ (1,0) [0|255] ""  PC
 SG_ E2P_Cfg2_SW_Ver_Byte12 : 24|8@1+ (1,0) [0|255] ""  PC
 SG_ E2P_Cfg2_SW_Ver_Byte13 : 32|8@1+ (1,0) [0|255] ""  PC
 SG_ E2P_Cfg2_SW_Ver_Byte14 : 40|8@1+ (1,0) [0|255] ""  PC
 SG_ E2P_Cfg2_SW_Ver_Byte15 : 48|8@1+ (1,0) [0|255] ""  PC
 SG_ E2P_Cfg2_SW_Ver_Byte16 : 56|8@1+ (1,0) [0|255] ""  PC

BO_ 2483351201 E2P_Cfg2__17: 8 ETH
 SG_ E2P_Cfg2_SW_Ver_Byte9 : 0|8@1+ (1,0) [0|255] ""  PC
 SG_ E2P_Cfg2_SW_Ver_Byte10 : 8|8@1+ (1,0) [0|255] ""  PC
 SG_ E2P_Cfg2_SW_Ver_Byte11 : 16|8@1+ (1,0) [0|255] ""  PC
 SG_ E2P_Cfg2_SW_Ver_Byte12 : 24|8@1+ (1,0) [0|255] ""  PC
 SG_ E2P_Cfg2_SW_Ver_Byte13 : 32|8@1+ (1,0) [0|255] ""  PC
 SG_ E2P_Cfg2_SW_Ver_Byte14 : 40|8@1+ (1,0) [0|255] ""  PC
 SG_ E2P_Cfg2_SW_Ver_Byte15 : 48|8@1+ (1,0) [0|255] ""  PC
 SG_ E2P_Cfg2_SW_Ver_Byte16 : 56|8@1+ (1,0) [0|255] ""  PC

BO_ 2483351202 E2P_Cfg2__18: 8 ETH
 SG_ E2P_Cfg2_SW_Ver_Byte9 : 0|8@1+ (1,0) [0|255] ""  PC
 SG_ E2P_Cfg2_SW_Ver_Byte10 : 8|8@1+ (1,0) [0|255] ""  PC
 SG_ E2P_Cfg2_SW_Ver_Byte11 : 16|8@1+ (1,0) [0|255] ""  PC
 SG_ E2P_Cfg2_SW_Ver_Byte12 : 24|8@1+ (1,0) [0|255] ""  PC
 SG_ E2P_Cfg2_SW_Ver_Byte13 : 32|8@1+ (1,0) [0|255] ""  PC
 SG_ E2P_Cfg2_SW_Ver_Byte14 : 40|8@1+ (1,0) [0|255] ""  PC
 SG_ E2P_Cfg2_SW_Ver_Byte15 : 48|8@1+ (1,0) [0|255] ""  PC
 SG_ E2P_Cfg2_SW_Ver_Byte16 : 56|8@1+ (1,0) [0|255] ""  PC

BO_ 2483351203 E2P_Cfg2__19: 8 ETH
 SG_ E2P_Cfg2_SW_Ver_Byte9 : 0|8@1+ (1,0) [0|255] ""  PC
 SG_ E2P_Cfg2_SW_Ver_Byte10 : 8|8@1+ (1,0) [0|255] ""  PC
 SG_ E2P_Cfg2_SW_Ver_Byte11 : 16|8@1+ (1,0) [0|255] ""  PC
 SG_ E2P_Cfg2_SW_Ver_Byte12 : 24|8@1+ (1,0) [0|255] ""  PC
 SG_ E2P_Cfg2_SW_Ver_Byte13 : 32|8@1+ (1,0) [0|255] ""  PC
 SG_ E2P_Cfg2_SW_Ver_Byte14 : 40|8@1+ (1,0) [0|255] ""  PC
 SG_ E2P_Cfg2_SW_Ver_Byte15 : 48|8@1+ (1,0) [0|255] ""  PC
 SG_ E2P_Cfg2_SW_Ver_Byte16 : 56|8@1+ (1,0) [0|255] ""  PC

BO_ 2483351204 E2P_Cfg2__20: 8 ETH
 SG_ E2P_Cfg2_SW_Ver_Byte9 : 0|8@1+ (1,0) [0|255] ""  PC
 SG_ E2P_Cfg2_SW_Ver_Byte10 : 8|8@1+ (1,0) [0|255] ""  PC
 SG_ E2P_Cfg2_SW_Ver_Byte11 : 16|8@1+ (1,0) [0|255] ""  PC
 SG_ E2P_Cfg2_SW_Ver_Byte12 : 24|8@1+ (1,0) [0|255] ""  PC
 SG_ E2P_Cfg2_SW_Ver_Byte13 : 32|8@1+ (1,0) [0|255] ""  PC
 SG_ E2P_Cfg2_SW_Ver_Byte14 : 40|8@1+ (1,0) [0|255] ""  PC
 SG_ E2P_Cfg2_SW_Ver_Byte15 : 48|8@1+ (1,0) [0|255] ""  PC
 SG_ E2P_Cfg2_SW_Ver_Byte16 : 56|8@1+ (1,0) [0|255] ""  PC

BO_ 2483351205 E2P_Cfg2__21: 8 ETH
 SG_ E2P_Cfg2_SW_Ver_Byte9 : 0|8@1+ (1,0) [0|255] ""  PC
 SG_ E2P_Cfg2_SW_Ver_Byte10 : 8|8@1+ (1,0) [0|255] ""  PC
 SG_ E2P_Cfg2_SW_Ver_Byte11 : 16|8@1+ (1,0) [0|255] ""  PC
 SG_ E2P_Cfg2_SW_Ver_Byte12 : 24|8@1+ (1,0) [0|255] ""  PC
 SG_ E2P_Cfg2_SW_Ver_Byte13 : 32|8@1+ (1,0) [0|255] ""  PC
 SG_ E2P_Cfg2_SW_Ver_Byte14 : 40|8@1+ (1,0) [0|255] ""  PC
 SG_ E2P_Cfg2_SW_Ver_Byte15 : 48|8@1+ (1,0) [0|255] ""  PC
 SG_ E2P_Cfg2_SW_Ver_Byte16 : 56|8@1+ (1,0) [0|255] ""  PC

BO_ 2483351206 E2P_Cfg2__22: 8 ETH
 SG_ E2P_Cfg2_SW_Ver_Byte9 : 0|8@1+ (1,0) [0|255] ""  PC
 SG_ E2P_Cfg2_SW_Ver_Byte10 : 8|8@1+ (1,0) [0|255] ""  PC
 SG_ E2P_Cfg2_SW_Ver_Byte11 : 16|8@1+ (1,0) [0|255] ""  PC
 SG_ E2P_Cfg2_SW_Ver_Byte12 : 24|8@1+ (1,0) [0|255] ""  PC
 SG_ E2P_Cfg2_SW_Ver_Byte13 : 32|8@1+ (1,0) [0|255] ""  PC
 SG_ E2P_Cfg2_SW_Ver_Byte14 : 40|8@1+ (1,0) [0|255] ""  PC
 SG_ E2P_Cfg2_SW_Ver_Byte15 : 48|8@1+ (1,0) [0|255] ""  PC
 SG_ E2P_Cfg2_SW_Ver_Byte16 : 56|8@1+ (1,0) [0|255] ""  PC

BO_ 2483351207 E2P_Cfg2__23: 8 ETH
 SG_ E2P_Cfg2_SW_Ver_Byte9 : 0|8@1+ (1,0) [0|255] ""  PC
 SG_ E2P_Cfg2_SW_Ver_Byte10 : 8|8@1+ (1,0) [0|255] ""  PC
 SG_ E2P_Cfg2_SW_Ver_Byte11 : 16|8@1+ (1,0) [0|255] ""  PC
 SG_ E2P_Cfg2_SW_Ver_Byte12 : 24|8@1+ (1,0) [0|255] ""  PC
 SG_ E2P_Cfg2_SW_Ver_Byte13 : 32|8@1+ (1,0) [0|255] ""  PC
 SG_ E2P_Cfg2_SW_Ver_Byte14 : 40|8@1+ (1,0) [0|255] ""  PC
 SG_ E2P_Cfg2_SW_Ver_Byte15 : 48|8@1+ (1,0) [0|255] ""  PC
 SG_ E2P_Cfg2_SW_Ver_Byte16 : 56|8@1+ (1,0) [0|255] ""  PC

BO_ 2483351208 E2P_Cfg2__24: 8 ETH
 SG_ E2P_Cfg2_SW_Ver_Byte9 : 0|8@1+ (1,0) [0|255] ""  PC
 SG_ E2P_Cfg2_SW_Ver_Byte10 : 8|8@1+ (1,0) [0|255] ""  PC
 SG_ E2P_Cfg2_SW_Ver_Byte11 : 16|8@1+ (1,0) [0|255] ""  PC
 SG_ E2P_Cfg2_SW_Ver_Byte12 : 24|8@1+ (1,0) [0|255] ""  PC
 SG_ E2P_Cfg2_SW_Ver_Byte13 : 32|8@1+ (1,0) [0|255] ""  PC
 SG_ E2P_Cfg2_SW_Ver_Byte14 : 40|8@1+ (1,0) [0|255] ""  PC
 SG_ E2P_Cfg2_SW_Ver_Byte15 : 48|8@1+ (1,0) [0|255] ""  PC
 SG_ E2P_Cfg2_SW_Ver_Byte16 : 56|8@1+ (1,0) [0|255] ""  PC

BO_ 2483351209 E2P_Cfg2__25: 8 ETH
 SG_ E2P_Cfg2_SW_Ver_Byte9 : 0|8@1+ (1,0) [0|255] ""  PC
 SG_ E2P_Cfg2_SW_Ver_Byte10 : 8|8@1+ (1,0) [0|255] ""  PC
 SG_ E2P_Cfg2_SW_Ver_Byte11 : 16|8@1+ (1,0) [0|255] ""  PC
 SG_ E2P_Cfg2_SW_Ver_Byte12 : 24|8@1+ (1,0) [0|255] ""  PC
 SG_ E2P_Cfg2_SW_Ver_Byte13 : 32|8@1+ (1,0) [0|255] ""  PC
 SG_ E2P_Cfg2_SW_Ver_Byte14 : 40|8@1+ (1,0) [0|255] ""  PC
 SG_ E2P_Cfg2_SW_Ver_Byte15 : 48|8@1+ (1,0) [0|255] ""  PC
 SG_ E2P_Cfg2_SW_Ver_Byte16 : 56|8@1+ (1,0) [0|255] ""  PC

BO_ 2483351210 E2P_Cfg2__26: 8 ETH
 SG_ E2P_Cfg2_SW_Ver_Byte9 : 0|8@1+ (1,0) [0|255] ""  PC
 SG_ E2P_Cfg2_SW_Ver_Byte10 : 8|8@1+ (1,0) [0|255] ""  PC
 SG_ E2P_Cfg2_SW_Ver_Byte11 : 16|8@1+ (1,0) [0|255] ""  PC
 SG_ E2P_Cfg2_SW_Ver_Byte12 : 24|8@1+ (1,0) [0|255] ""  PC
 SG_ E2P_Cfg2_SW_Ver_Byte13 : 32|8@1+ (1,0) [0|255] ""  PC
 SG_ E2P_Cfg2_SW_Ver_Byte14 : 40|8@1+ (1,0) [0|255] ""  PC
 SG_ E2P_Cfg2_SW_Ver_Byte15 : 48|8@1+ (1,0) [0|255] ""  PC
 SG_ E2P_Cfg2_SW_Ver_Byte16 : 56|8@1+ (1,0) [0|255] ""  PC

BO_ 2483351211 E2P_Cfg2__27: 8 ETH
 SG_ E2P_Cfg2_SW_Ver_Byte9 : 0|8@1+ (1,0) [0|255] ""  PC
 SG_ E2P_Cfg2_SW_Ver_Byte10 : 8|8@1+ (1,0) [0|255] ""  PC
 SG_ E2P_Cfg2_SW_Ver_Byte11 : 16|8@1+ (1,0) [0|255] ""  PC
 SG_ E2P_Cfg2_SW_Ver_Byte12 : 24|8@1+ (1,0) [0|255] ""  PC
 SG_ E2P_Cfg2_SW_Ver_Byte13 : 32|8@1+ (1,0) [0|255] ""  PC
 SG_ E2P_Cfg2_SW_Ver_Byte14 : 40|8@1+ (1,0) [0|255] ""  PC
 SG_ E2P_Cfg2_SW_Ver_Byte15 : 48|8@1+ (1,0) [0|255] ""  PC
 SG_ E2P_Cfg2_SW_Ver_Byte16 : 56|8@1+ (1,0) [0|255] ""  PC

BO_ 2483351212 E2P_Cfg2__28: 8 ETH
 SG_ E2P_Cfg2_SW_Ver_Byte9 : 0|8@1+ (1,0) [0|255] ""  PC
 SG_ E2P_Cfg2_SW_Ver_Byte10 : 8|8@1+ (1,0) [0|255] ""  PC
 SG_ E2P_Cfg2_SW_Ver_Byte11 : 16|8@1+ (1,0) [0|255] ""  PC
 SG_ E2P_Cfg2_SW_Ver_Byte12 : 24|8@1+ (1,0) [0|255] ""  PC
 SG_ E2P_Cfg2_SW_Ver_Byte13 : 32|8@1+ (1,0) [0|255] ""  PC
 SG_ E2P_Cfg2_SW_Ver_Byte14 : 40|8@1+ (1,0) [0|255] ""  PC
 SG_ E2P_Cfg2_SW_Ver_Byte15 : 48|8@1+ (1,0) [0|255] ""  PC
 SG_ E2P_Cfg2_SW_Ver_Byte16 : 56|8@1+ (1,0) [0|255] ""  PC

BO_ 2483351213 E2P_Cfg2__29: 8 ETH
 SG_ E2P_Cfg2_SW_Ver_Byte9 : 0|8@1+ (1,0) [0|255] ""  PC
 SG_ E2P_Cfg2_SW_Ver_Byte10 : 8|8@1+ (1,0) [0|255] ""  PC
 SG_ E2P_Cfg2_SW_Ver_Byte11 : 16|8@1+ (1,0) [0|255] ""  PC
 SG_ E2P_Cfg2_SW_Ver_Byte12 : 24|8@1+ (1,0) [0|255] ""  PC
 SG_ E2P_Cfg2_SW_Ver_Byte13 : 32|8@1+ (1,0) [0|255] ""  PC
 SG_ E2P_Cfg2_SW_Ver_Byte14 : 40|8@1+ (1,0) [0|255] ""  PC
 SG_ E2P_Cfg2_SW_Ver_Byte15 : 48|8@1+ (1,0) [0|255] ""  PC
 SG_ E2P_Cfg2_SW_Ver_Byte16 : 56|8@1+ (1,0) [0|255] ""  PC

BO_ 2483351214 E2P_Cfg2__30: 8 ETH
 SG_ E2P_Cfg2_SW_Ver_Byte9 : 0|8@1+ (1,0) [0|255] ""  PC
 SG_ E2P_Cfg2_SW_Ver_Byte10 : 8|8@1+ (1,0) [0|255] ""  PC
 SG_ E2P_Cfg2_SW_Ver_Byte11 : 16|8@1+ (1,0) [0|255] ""  PC
 SG_ E2P_Cfg2_SW_Ver_Byte12 : 24|8@1+ (1,0) [0|255] ""  PC
 SG_ E2P_Cfg2_SW_Ver_Byte13 : 32|8@1+ (1,0) [0|255] ""  PC
 SG_ E2P_Cfg2_SW_Ver_Byte14 : 40|8@1+ (1,0) [0|255] ""  PC
 SG_ E2P_Cfg2_SW_Ver_Byte15 : 48|8@1+ (1,0) [0|255] ""  PC
 SG_ E2P_Cfg2_SW_Ver_Byte16 : 56|8@1+ (1,0) [0|255] ""  PC

BO_ 2483351215 E2P_Cfg2__31: 8 ETH
 SG_ E2P_Cfg2_SW_Ver_Byte9 : 0|8@1+ (1,0) [0|255] ""  PC
 SG_ E2P_Cfg2_SW_Ver_Byte10 : 8|8@1+ (1,0) [0|255] ""  PC
 SG_ E2P_Cfg2_SW_Ver_Byte11 : 16|8@1+ (1,0) [0|255] ""  PC
 SG_ E2P_Cfg2_SW_Ver_Byte12 : 24|8@1+ (1,0) [0|255] ""  PC
 SG_ E2P_Cfg2_SW_Ver_Byte13 : 32|8@1+ (1,0) [0|255] ""  PC
 SG_ E2P_Cfg2_SW_Ver_Byte14 : 40|8@1+ (1,0) [0|255] ""  PC
 SG_ E2P_Cfg2_SW_Ver_Byte15 : 48|8@1+ (1,0) [0|255] ""  PC
 SG_ E2P_Cfg2_SW_Ver_Byte16 : 56|8@1+ (1,0) [0|255] ""  PC

BO_ 2483416721 E2P_Cfg3__01: 8 ETH
 SG_ E2P_Cfg3_HW_Ver_Byte1 : 0|8@1+ (1,0) [0|255] ""  PC
 SG_ E2P_Cfg3_HW_Ver_Byte2 : 8|8@1+ (1,0) [0|255] ""  PC
 SG_ E2P_Cfg3_HW_Ver_Byte3 : 16|8@1+ (1,0) [0|255] ""  PC
 SG_ E2P_Cfg3_HW_Ver_Byte4 : 24|8@1+ (1,0) [0|255] ""  PC
 SG_ E2P_Cfg3_HW_Ver_Byte5 : 32|8@1+ (1,0) [0|255] ""  PC
 SG_ E2P_Cfg3_HW_Ver_Byte6 : 40|8@1+ (1,0) [0|255] ""  PC
 SG_ E2P_Cfg3_HW_Ver_Byte7 : 48|8@1+ (1,0) [0|255] ""  PC
 SG_ E2P_Cfg3_HW_Ver_Byte8 : 56|8@1+ (1,0) [0|255] ""  PC

BO_ 2483416722 E2P_Cfg3__02: 8 ETH
 SG_ E2P_Cfg3_HW_Ver_Byte1 : 0|8@1+ (1,0) [0|255] ""  PC
 SG_ E2P_Cfg3_HW_Ver_Byte2 : 8|8@1+ (1,0) [0|255] ""  PC
 SG_ E2P_Cfg3_HW_Ver_Byte3 : 16|8@1+ (1,0) [0|255] ""  PC
 SG_ E2P_Cfg3_HW_Ver_Byte4 : 24|8@1+ (1,0) [0|255] ""  PC
 SG_ E2P_Cfg3_HW_Ver_Byte5 : 32|8@1+ (1,0) [0|255] ""  PC
 SG_ E2P_Cfg3_HW_Ver_Byte6 : 40|8@1+ (1,0) [0|255] ""  PC
 SG_ E2P_Cfg3_HW_Ver_Byte7 : 48|8@1+ (1,0) [0|255] ""  PC
 SG_ E2P_Cfg3_HW_Ver_Byte8 : 56|8@1+ (1,0) [0|255] ""  PC

BO_ 2483416723 E2P_Cfg3__03: 8 ETH
 SG_ E2P_Cfg3_HW_Ver_Byte1 : 0|8@1+ (1,0) [0|255] ""  PC
 SG_ E2P_Cfg3_HW_Ver_Byte2 : 8|8@1+ (1,0) [0|255] ""  PC
 SG_ E2P_Cfg3_HW_Ver_Byte3 : 16|8@1+ (1,0) [0|255] ""  PC
 SG_ E2P_Cfg3_HW_Ver_Byte4 : 24|8@1+ (1,0) [0|255] ""  PC
 SG_ E2P_Cfg3_HW_Ver_Byte5 : 32|8@1+ (1,0) [0|255] ""  PC
 SG_ E2P_Cfg3_HW_Ver_Byte6 : 40|8@1+ (1,0) [0|255] ""  PC
 SG_ E2P_Cfg3_HW_Ver_Byte7 : 48|8@1+ (1,0) [0|255] ""  PC
 SG_ E2P_Cfg3_HW_Ver_Byte8 : 56|8@1+ (1,0) [0|255] ""  PC

BO_ 2483416724 E2P_Cfg3__04: 8 ETH
 SG_ E2P_Cfg3_HW_Ver_Byte1 : 0|8@1+ (1,0) [0|255] ""  PC
 SG_ E2P_Cfg3_HW_Ver_Byte2 : 8|8@1+ (1,0) [0|255] ""  PC
 SG_ E2P_Cfg3_HW_Ver_Byte3 : 16|8@1+ (1,0) [0|255] ""  PC
 SG_ E2P_Cfg3_HW_Ver_Byte4 : 24|8@1+ (1,0) [0|255] ""  PC
 SG_ E2P_Cfg3_HW_Ver_Byte5 : 32|8@1+ (1,0) [0|255] ""  PC
 SG_ E2P_Cfg3_HW_Ver_Byte6 : 40|8@1+ (1,0) [0|255] ""  PC
 SG_ E2P_Cfg3_HW_Ver_Byte7 : 48|8@1+ (1,0) [0|255] ""  PC
 SG_ E2P_Cfg3_HW_Ver_Byte8 : 56|8@1+ (1,0) [0|255] ""  PC

BO_ 2483416725 E2P_Cfg3__05: 8 ETH
 SG_ E2P_Cfg3_HW_Ver_Byte1 : 0|8@1+ (1,0) [0|255] ""  PC
 SG_ E2P_Cfg3_HW_Ver_Byte2 : 8|8@1+ (1,0) [0|255] ""  PC
 SG_ E2P_Cfg3_HW_Ver_Byte3 : 16|8@1+ (1,0) [0|255] ""  PC
 SG_ E2P_Cfg3_HW_Ver_Byte4 : 24|8@1+ (1,0) [0|255] ""  PC
 SG_ E2P_Cfg3_HW_Ver_Byte5 : 32|8@1+ (1,0) [0|255] ""  PC
 SG_ E2P_Cfg3_HW_Ver_Byte6 : 40|8@1+ (1,0) [0|255] ""  PC
 SG_ E2P_Cfg3_HW_Ver_Byte7 : 48|8@1+ (1,0) [0|255] ""  PC
 SG_ E2P_Cfg3_HW_Ver_Byte8 : 56|8@1+ (1,0) [0|255] ""  PC

BO_ 2483416726 E2P_Cfg3__06: 8 ETH
 SG_ E2P_Cfg3_HW_Ver_Byte1 : 0|8@1+ (1,0) [0|255] ""  PC
 SG_ E2P_Cfg3_HW_Ver_Byte2 : 8|8@1+ (1,0) [0|255] ""  PC
 SG_ E2P_Cfg3_HW_Ver_Byte3 : 16|8@1+ (1,0) [0|255] ""  PC
 SG_ E2P_Cfg3_HW_Ver_Byte4 : 24|8@1+ (1,0) [0|255] ""  PC
 SG_ E2P_Cfg3_HW_Ver_Byte5 : 32|8@1+ (1,0) [0|255] ""  PC
 SG_ E2P_Cfg3_HW_Ver_Byte6 : 40|8@1+ (1,0) [0|255] ""  PC
 SG_ E2P_Cfg3_HW_Ver_Byte7 : 48|8@1+ (1,0) [0|255] ""  PC
 SG_ E2P_Cfg3_HW_Ver_Byte8 : 56|8@1+ (1,0) [0|255] ""  PC

BO_ 2483416727 E2P_Cfg3__07: 8 ETH
 SG_ E2P_Cfg3_HW_Ver_Byte1 : 0|8@1+ (1,0) [0|255] ""  PC
 SG_ E2P_Cfg3_HW_Ver_Byte2 : 8|8@1+ (1,0) [0|255] ""  PC
 SG_ E2P_Cfg3_HW_Ver_Byte3 : 16|8@1+ (1,0) [0|255] ""  PC
 SG_ E2P_Cfg3_HW_Ver_Byte4 : 24|8@1+ (1,0) [0|255] ""  PC
 SG_ E2P_Cfg3_HW_Ver_Byte5 : 32|8@1+ (1,0) [0|255] ""  PC
 SG_ E2P_Cfg3_HW_Ver_Byte6 : 40|8@1+ (1,0) [0|255] ""  PC
 SG_ E2P_Cfg3_HW_Ver_Byte7 : 48|8@1+ (1,0) [0|255] ""  PC
 SG_ E2P_Cfg3_HW_Ver_Byte8 : 56|8@1+ (1,0) [0|255] ""  PC

BO_ 2483416728 E2P_Cfg3__08: 8 ETH
 SG_ E2P_Cfg3_HW_Ver_Byte1 : 0|8@1+ (1,0) [0|255] ""  PC
 SG_ E2P_Cfg3_HW_Ver_Byte2 : 8|8@1+ (1,0) [0|255] ""  PC
 SG_ E2P_Cfg3_HW_Ver_Byte3 : 16|8@1+ (1,0) [0|255] ""  PC
 SG_ E2P_Cfg3_HW_Ver_Byte4 : 24|8@1+ (1,0) [0|255] ""  PC
 SG_ E2P_Cfg3_HW_Ver_Byte5 : 32|8@1+ (1,0) [0|255] ""  PC
 SG_ E2P_Cfg3_HW_Ver_Byte6 : 40|8@1+ (1,0) [0|255] ""  PC
 SG_ E2P_Cfg3_HW_Ver_Byte7 : 48|8@1+ (1,0) [0|255] ""  PC
 SG_ E2P_Cfg3_HW_Ver_Byte8 : 56|8@1+ (1,0) [0|255] ""  PC

BO_ 2483416729 E2P_Cfg3__09: 8 ETH
 SG_ E2P_Cfg3_HW_Ver_Byte1 : 0|8@1+ (1,0) [0|255] ""  PC
 SG_ E2P_Cfg3_HW_Ver_Byte2 : 8|8@1+ (1,0) [0|255] ""  PC
 SG_ E2P_Cfg3_HW_Ver_Byte3 : 16|8@1+ (1,0) [0|255] ""  PC
 SG_ E2P_Cfg3_HW_Ver_Byte4 : 24|8@1+ (1,0) [0|255] ""  PC
 SG_ E2P_Cfg3_HW_Ver_Byte5 : 32|8@1+ (1,0) [0|255] ""  PC
 SG_ E2P_Cfg3_HW_Ver_Byte6 : 40|8@1+ (1,0) [0|255] ""  PC
 SG_ E2P_Cfg3_HW_Ver_Byte7 : 48|8@1+ (1,0) [0|255] ""  PC
 SG_ E2P_Cfg3_HW_Ver_Byte8 : 56|8@1+ (1,0) [0|255] ""  PC

BO_ 2483416730 E2P_Cfg3__10: 8 ETH
 SG_ E2P_Cfg3_HW_Ver_Byte1 : 0|8@1+ (1,0) [0|255] ""  PC
 SG_ E2P_Cfg3_HW_Ver_Byte2 : 8|8@1+ (1,0) [0|255] ""  PC
 SG_ E2P_Cfg3_HW_Ver_Byte3 : 16|8@1+ (1,0) [0|255] ""  PC
 SG_ E2P_Cfg3_HW_Ver_Byte4 : 24|8@1+ (1,0) [0|255] ""  PC
 SG_ E2P_Cfg3_HW_Ver_Byte5 : 32|8@1+ (1,0) [0|255] ""  PC
 SG_ E2P_Cfg3_HW_Ver_Byte6 : 40|8@1+ (1,0) [0|255] ""  PC
 SG_ E2P_Cfg3_HW_Ver_Byte7 : 48|8@1+ (1,0) [0|255] ""  PC
 SG_ E2P_Cfg3_HW_Ver_Byte8 : 56|8@1+ (1,0) [0|255] ""  PC

BO_ 2483416731 E2P_Cfg3__11: 8 ETH
 SG_ E2P_Cfg3_HW_Ver_Byte1 : 0|8@1+ (1,0) [0|255] ""  PC
 SG_ E2P_Cfg3_HW_Ver_Byte2 : 8|8@1+ (1,0) [0|255] ""  PC
 SG_ E2P_Cfg3_HW_Ver_Byte3 : 16|8@1+ (1,0) [0|255] ""  PC
 SG_ E2P_Cfg3_HW_Ver_Byte4 : 24|8@1+ (1,0) [0|255] ""  PC
 SG_ E2P_Cfg3_HW_Ver_Byte5 : 32|8@1+ (1,0) [0|255] ""  PC
 SG_ E2P_Cfg3_HW_Ver_Byte6 : 40|8@1+ (1,0) [0|255] ""  PC
 SG_ E2P_Cfg3_HW_Ver_Byte7 : 48|8@1+ (1,0) [0|255] ""  PC
 SG_ E2P_Cfg3_HW_Ver_Byte8 : 56|8@1+ (1,0) [0|255] ""  PC

BO_ 2483416732 E2P_Cfg3__12: 8 ETH
 SG_ E2P_Cfg3_HW_Ver_Byte1 : 0|8@1+ (1,0) [0|255] ""  PC
 SG_ E2P_Cfg3_HW_Ver_Byte2 : 8|8@1+ (1,0) [0|255] ""  PC
 SG_ E2P_Cfg3_HW_Ver_Byte3 : 16|8@1+ (1,0) [0|255] ""  PC
 SG_ E2P_Cfg3_HW_Ver_Byte4 : 24|8@1+ (1,0) [0|255] ""  PC
 SG_ E2P_Cfg3_HW_Ver_Byte5 : 32|8@1+ (1,0) [0|255] ""  PC
 SG_ E2P_Cfg3_HW_Ver_Byte6 : 40|8@1+ (1,0) [0|255] ""  PC
 SG_ E2P_Cfg3_HW_Ver_Byte7 : 48|8@1+ (1,0) [0|255] ""  PC
 SG_ E2P_Cfg3_HW_Ver_Byte8 : 56|8@1+ (1,0) [0|255] ""  PC

BO_ 2483416733 E2P_Cfg3__13: 8 ETH
 SG_ E2P_Cfg3_HW_Ver_Byte1 : 0|8@1+ (1,0) [0|255] ""  PC
 SG_ E2P_Cfg3_HW_Ver_Byte2 : 8|8@1+ (1,0) [0|255] ""  PC
 SG_ E2P_Cfg3_HW_Ver_Byte3 : 16|8@1+ (1,0) [0|255] ""  PC
 SG_ E2P_Cfg3_HW_Ver_Byte4 : 24|8@1+ (1,0) [0|255] ""  PC
 SG_ E2P_Cfg3_HW_Ver_Byte5 : 32|8@1+ (1,0) [0|255] ""  PC
 SG_ E2P_Cfg3_HW_Ver_Byte6 : 40|8@1+ (1,0) [0|255] ""  PC
 SG_ E2P_Cfg3_HW_Ver_Byte7 : 48|8@1+ (1,0) [0|255] ""  PC
 SG_ E2P_Cfg3_HW_Ver_Byte8 : 56|8@1+ (1,0) [0|255] ""  PC

BO_ 2483416734 E2P_Cfg3__14: 8 ETH
 SG_ E2P_Cfg3_HW_Ver_Byte1 : 0|8@1+ (1,0) [0|255] ""  PC
 SG_ E2P_Cfg3_HW_Ver_Byte2 : 8|8@1+ (1,0) [0|255] ""  PC
 SG_ E2P_Cfg3_HW_Ver_Byte3 : 16|8@1+ (1,0) [0|255] ""  PC
 SG_ E2P_Cfg3_HW_Ver_Byte4 : 24|8@1+ (1,0) [0|255] ""  PC
 SG_ E2P_Cfg3_HW_Ver_Byte5 : 32|8@1+ (1,0) [0|255] ""  PC
 SG_ E2P_Cfg3_HW_Ver_Byte6 : 40|8@1+ (1,0) [0|255] ""  PC
 SG_ E2P_Cfg3_HW_Ver_Byte7 : 48|8@1+ (1,0) [0|255] ""  PC
 SG_ E2P_Cfg3_HW_Ver_Byte8 : 56|8@1+ (1,0) [0|255] ""  PC

BO_ 2483416735 E2P_Cfg3__15: 8 ETH
 SG_ E2P_Cfg3_HW_Ver_Byte1 : 0|8@1+ (1,0) [0|255] ""  PC
 SG_ E2P_Cfg3_HW_Ver_Byte2 : 8|8@1+ (1,0) [0|255] ""  PC
 SG_ E2P_Cfg3_HW_Ver_Byte3 : 16|8@1+ (1,0) [0|255] ""  PC
 SG_ E2P_Cfg3_HW_Ver_Byte4 : 24|8@1+ (1,0) [0|255] ""  PC
 SG_ E2P_Cfg3_HW_Ver_Byte5 : 32|8@1+ (1,0) [0|255] ""  PC
 SG_ E2P_Cfg3_HW_Ver_Byte6 : 40|8@1+ (1,0) [0|255] ""  PC
 SG_ E2P_Cfg3_HW_Ver_Byte7 : 48|8@1+ (1,0) [0|255] ""  PC
 SG_ E2P_Cfg3_HW_Ver_Byte8 : 56|8@1+ (1,0) [0|255] ""  PC

BO_ 2483416736 E2P_Cfg3__16: 8 ETH
 SG_ E2P_Cfg3_HW_Ver_Byte1 : 0|8@1+ (1,0) [0|255] ""  PC
 SG_ E2P_Cfg3_HW_Ver_Byte2 : 8|8@1+ (1,0) [0|255] ""  PC
 SG_ E2P_Cfg3_HW_Ver_Byte3 : 16|8@1+ (1,0) [0|255] ""  PC
 SG_ E2P_Cfg3_HW_Ver_Byte4 : 24|8@1+ (1,0) [0|255] ""  PC
 SG_ E2P_Cfg3_HW_Ver_Byte5 : 32|8@1+ (1,0) [0|255] ""  PC
 SG_ E2P_Cfg3_HW_Ver_Byte6 : 40|8@1+ (1,0) [0|255] ""  PC
 SG_ E2P_Cfg3_HW_Ver_Byte7 : 48|8@1+ (1,0) [0|255] ""  PC
 SG_ E2P_Cfg3_HW_Ver_Byte8 : 56|8@1+ (1,0) [0|255] ""  PC

BO_ 2483416737 E2P_Cfg3__17: 8 ETH
 SG_ E2P_Cfg3_HW_Ver_Byte1 : 0|8@1+ (1,0) [0|255] ""  PC
 SG_ E2P_Cfg3_HW_Ver_Byte2 : 8|8@1+ (1,0) [0|255] ""  PC
 SG_ E2P_Cfg3_HW_Ver_Byte3 : 16|8@1+ (1,0) [0|255] ""  PC
 SG_ E2P_Cfg3_HW_Ver_Byte4 : 24|8@1+ (1,0) [0|255] ""  PC
 SG_ E2P_Cfg3_HW_Ver_Byte5 : 32|8@1+ (1,0) [0|255] ""  PC
 SG_ E2P_Cfg3_HW_Ver_Byte6 : 40|8@1+ (1,0) [0|255] ""  PC
 SG_ E2P_Cfg3_HW_Ver_Byte7 : 48|8@1+ (1,0) [0|255] ""  PC
 SG_ E2P_Cfg3_HW_Ver_Byte8 : 56|8@1+ (1,0) [0|255] ""  PC

BO_ 2483416738 E2P_Cfg3__18: 8 ETH
 SG_ E2P_Cfg3_HW_Ver_Byte1 : 0|8@1+ (1,0) [0|255] ""  PC
 SG_ E2P_Cfg3_HW_Ver_Byte2 : 8|8@1+ (1,0) [0|255] ""  PC
 SG_ E2P_Cfg3_HW_Ver_Byte3 : 16|8@1+ (1,0) [0|255] ""  PC
 SG_ E2P_Cfg3_HW_Ver_Byte4 : 24|8@1+ (1,0) [0|255] ""  PC
 SG_ E2P_Cfg3_HW_Ver_Byte5 : 32|8@1+ (1,0) [0|255] ""  PC
 SG_ E2P_Cfg3_HW_Ver_Byte6 : 40|8@1+ (1,0) [0|255] ""  PC
 SG_ E2P_Cfg3_HW_Ver_Byte7 : 48|8@1+ (1,0) [0|255] ""  PC
 SG_ E2P_Cfg3_HW_Ver_Byte8 : 56|8@1+ (1,0) [0|255] ""  PC

BO_ 2483416739 E2P_Cfg3__19: 8 ETH
 SG_ E2P_Cfg3_HW_Ver_Byte1 : 0|8@1+ (1,0) [0|255] ""  PC
 SG_ E2P_Cfg3_HW_Ver_Byte2 : 8|8@1+ (1,0) [0|255] ""  PC
 SG_ E2P_Cfg3_HW_Ver_Byte3 : 16|8@1+ (1,0) [0|255] ""  PC
 SG_ E2P_Cfg3_HW_Ver_Byte4 : 24|8@1+ (1,0) [0|255] ""  PC
 SG_ E2P_Cfg3_HW_Ver_Byte5 : 32|8@1+ (1,0) [0|255] ""  PC
 SG_ E2P_Cfg3_HW_Ver_Byte6 : 40|8@1+ (1,0) [0|255] ""  PC
 SG_ E2P_Cfg3_HW_Ver_Byte7 : 48|8@1+ (1,0) [0|255] ""  PC
 SG_ E2P_Cfg3_HW_Ver_Byte8 : 56|8@1+ (1,0) [0|255] ""  PC

BO_ 2483416740 E2P_Cfg3__20: 8 ETH
 SG_ E2P_Cfg3_HW_Ver_Byte1 : 0|8@1+ (1,0) [0|255] ""  PC
 SG_ E2P_Cfg3_HW_Ver_Byte2 : 8|8@1+ (1,0) [0|255] ""  PC
 SG_ E2P_Cfg3_HW_Ver_Byte3 : 16|8@1+ (1,0) [0|255] ""  PC
 SG_ E2P_Cfg3_HW_Ver_Byte4 : 24|8@1+ (1,0) [0|255] ""  PC
 SG_ E2P_Cfg3_HW_Ver_Byte5 : 32|8@1+ (1,0) [0|255] ""  PC
 SG_ E2P_Cfg3_HW_Ver_Byte6 : 40|8@1+ (1,0) [0|255] ""  PC
 SG_ E2P_Cfg3_HW_Ver_Byte7 : 48|8@1+ (1,0) [0|255] ""  PC
 SG_ E2P_Cfg3_HW_Ver_Byte8 : 56|8@1+ (1,0) [0|255] ""  PC

BO_ 2483416741 E2P_Cfg3__21: 8 ETH
 SG_ E2P_Cfg3_HW_Ver_Byte1 : 0|8@1+ (1,0) [0|255] ""  PC
 SG_ E2P_Cfg3_HW_Ver_Byte2 : 8|8@1+ (1,0) [0|255] ""  PC
 SG_ E2P_Cfg3_HW_Ver_Byte3 : 16|8@1+ (1,0) [0|255] ""  PC
 SG_ E2P_Cfg3_HW_Ver_Byte4 : 24|8@1+ (1,0) [0|255] ""  PC
 SG_ E2P_Cfg3_HW_Ver_Byte5 : 32|8@1+ (1,0) [0|255] ""  PC
 SG_ E2P_Cfg3_HW_Ver_Byte6 : 40|8@1+ (1,0) [0|255] ""  PC
 SG_ E2P_Cfg3_HW_Ver_Byte7 : 48|8@1+ (1,0) [0|255] ""  PC
 SG_ E2P_Cfg3_HW_Ver_Byte8 : 56|8@1+ (1,0) [0|255] ""  PC

BO_ 2483416742 E2P_Cfg3__22: 8 ETH
 SG_ E2P_Cfg3_HW_Ver_Byte1 : 0|8@1+ (1,0) [0|255] ""  PC
 SG_ E2P_Cfg3_HW_Ver_Byte2 : 8|8@1+ (1,0) [0|255] ""  PC
 SG_ E2P_Cfg3_HW_Ver_Byte3 : 16|8@1+ (1,0) [0|255] ""  PC
 SG_ E2P_Cfg3_HW_Ver_Byte4 : 24|8@1+ (1,0) [0|255] ""  PC
 SG_ E2P_Cfg3_HW_Ver_Byte5 : 32|8@1+ (1,0) [0|255] ""  PC
 SG_ E2P_Cfg3_HW_Ver_Byte6 : 40|8@1+ (1,0) [0|255] ""  PC
 SG_ E2P_Cfg3_HW_Ver_Byte7 : 48|8@1+ (1,0) [0|255] ""  PC
 SG_ E2P_Cfg3_HW_Ver_Byte8 : 56|8@1+ (1,0) [0|255] ""  PC

CM_ SG_ 2418601574 S2P_Cfg12_SW_Ver_Byte1_38 "CSC软件版本号最低字节Byte1对应的ASCII码(国产MCU)";
CM_ SG_ 2418601574 S2P_Cfg12_SW_Ver_Byte2_38 "CSC软件版本号Byte2对应的ASCII码(国产MCU)";
CM_ SG_ 2418601574 S2P_Cfg12_SW_Ver_Byte3_38 "CSC软件版本号Byte3对应的ASCII码(国产MCU)";
CM_ SG_ 2418601574 S2P_Cfg12_SW_Ver_Byte4_38 "CSC软件版本号Byte4对应的ASCII码(国产MCU)";
CM_ SG_ 2418601574 S2P_Cfg12_SW_Ver_Byte5_38 "CSC软件版本号Byte5对应的ASCII码(国产MCU)";
CM_ SG_ 2418601574 S2P_Cfg12_SW_Ver_Byte6_38 "CSC软件版本号Byte6对应的ASCII码(国产MCU)";
CM_ SG_ 2418601574 S2P_Cfg12_SW_Ver_Byte7_38 "CSC软件版本号Byte7对应的ASCII码(国产MCU)";
CM_ SG_ 2418601574 S2P_Cfg12_SW_Ver_Byte8_38 "CSC软件版本号Byte8对应的ASCII码(国产MCU)";
CM_ SG_ 2418601575 S2P_Cfg12_SW_Ver_Byte1_39 "CSC软件版本号最低字节Byte1对应的ASCII码(国产MCU)";
CM_ SG_ 2418601575 S2P_Cfg12_SW_Ver_Byte2_39 "CSC软件版本号Byte2对应的ASCII码(国产MCU)";
CM_ SG_ 2418601575 S2P_Cfg12_SW_Ver_Byte3_39 "CSC软件版本号Byte3对应的ASCII码(国产MCU)";
CM_ SG_ 2418601575 S2P_Cfg12_SW_Ver_Byte4_39 "CSC软件版本号Byte4对应的ASCII码(国产MCU)";
CM_ SG_ 2418601575 S2P_Cfg12_SW_Ver_Byte5_39 "CSC软件版本号Byte5对应的ASCII码(国产MCU)";
CM_ SG_ 2418601575 S2P_Cfg12_SW_Ver_Byte6_39 "CSC软件版本号Byte6对应的ASCII码(国产MCU)";
CM_ SG_ 2418601575 S2P_Cfg12_SW_Ver_Byte7_39 "CSC软件版本号Byte7对应的ASCII码(国产MCU)";
CM_ SG_ 2418601575 S2P_Cfg12_SW_Ver_Byte8_39 "CSC软件版本号Byte8对应的ASCII码(国产MCU)";
CM_ SG_ 2418601576 S2P_Cfg12_SW_Ver_Byte1_40 "CSC软件版本号最低字节Byte1对应的ASCII码(国产MCU)";
CM_ SG_ 2418601576 S2P_Cfg12_SW_Ver_Byte2_40 "CSC软件版本号Byte2对应的ASCII码(国产MCU)";
CM_ SG_ 2418601576 S2P_Cfg12_SW_Ver_Byte3_40 "CSC软件版本号Byte3对应的ASCII码(国产MCU)";
CM_ SG_ 2418601576 S2P_Cfg12_SW_Ver_Byte4_40 "CSC软件版本号Byte4对应的ASCII码(国产MCU)";
CM_ SG_ 2418601576 S2P_Cfg12_SW_Ver_Byte5_40 "CSC软件版本号Byte5对应的ASCII码(国产MCU)";
CM_ SG_ 2418601576 S2P_Cfg12_SW_Ver_Byte6_40 "CSC软件版本号Byte6对应的ASCII码(国产MCU)";
CM_ SG_ 2418601576 S2P_Cfg12_SW_Ver_Byte7_40 "CSC软件版本号Byte7对应的ASCII码(国产MCU)";
CM_ SG_ 2418601576 S2P_Cfg12_SW_Ver_Byte8_40 "CSC软件版本号Byte8对应的ASCII码(国产MCU)";
CM_ SG_ 2418601577 S2P_Cfg12_SW_Ver_Byte1_41 "CSC软件版本号最低字节Byte1对应的ASCII码(国产MCU)";
CM_ SG_ 2418601577 S2P_Cfg12_SW_Ver_Byte2_41 "CSC软件版本号Byte2对应的ASCII码(国产MCU)";
CM_ SG_ 2418601577 S2P_Cfg12_SW_Ver_Byte3_41 "CSC软件版本号Byte3对应的ASCII码(国产MCU)";
CM_ SG_ 2418601577 S2P_Cfg12_SW_Ver_Byte4_41 "CSC软件版本号Byte4对应的ASCII码(国产MCU)";
CM_ SG_ 2418601577 S2P_Cfg12_SW_Ver_Byte5_41 "CSC软件版本号Byte5对应的ASCII码(国产MCU)";
CM_ SG_ 2418601577 S2P_Cfg12_SW_Ver_Byte6_41 "CSC软件版本号Byte6对应的ASCII码(国产MCU)";
CM_ SG_ 2418601577 S2P_Cfg12_SW_Ver_Byte7_41 "CSC软件版本号Byte7对应的ASCII码(国产MCU)";
CM_ SG_ 2418601577 S2P_Cfg12_SW_Ver_Byte8_41 "CSC软件版本号Byte8对应的ASCII码(国产MCU)";
CM_ SG_ 2418601578 S2P_Cfg12_SW_Ver_Byte1_42 "CSC软件版本号最低字节Byte1对应的ASCII码(国产MCU)";
CM_ SG_ 2418601578 S2P_Cfg12_SW_Ver_Byte2_42 "CSC软件版本号Byte2对应的ASCII码(国产MCU)";
CM_ SG_ 2418601578 S2P_Cfg12_SW_Ver_Byte3_42 "CSC软件版本号Byte3对应的ASCII码(国产MCU)";
CM_ SG_ 2418601578 S2P_Cfg12_SW_Ver_Byte4_42 "CSC软件版本号Byte4对应的ASCII码(国产MCU)";
CM_ SG_ 2418601578 S2P_Cfg12_SW_Ver_Byte5_42 "CSC软件版本号Byte5对应的ASCII码(国产MCU)";
CM_ SG_ 2418601578 S2P_Cfg12_SW_Ver_Byte6_42 "CSC软件版本号Byte6对应的ASCII码(国产MCU)";
CM_ SG_ 2418601578 S2P_Cfg12_SW_Ver_Byte7_42 "CSC软件版本号Byte7对应的ASCII码(国产MCU)";
CM_ SG_ 2418601578 S2P_Cfg12_SW_Ver_Byte8_42 "CSC软件版本号Byte8对应的ASCII码(国产MCU)";
CM_ SG_ 2418601579 S2P_Cfg12_SW_Ver_Byte1_43 "CSC软件版本号最低字节Byte1对应的ASCII码(国产MCU)";
CM_ SG_ 2418601579 S2P_Cfg12_SW_Ver_Byte2_43 "CSC软件版本号Byte2对应的ASCII码(国产MCU)";
CM_ SG_ 2418601579 S2P_Cfg12_SW_Ver_Byte3_43 "CSC软件版本号Byte3对应的ASCII码(国产MCU)";
CM_ SG_ 2418601579 S2P_Cfg12_SW_Ver_Byte4_43 "CSC软件版本号Byte4对应的ASCII码(国产MCU)";
CM_ SG_ 2418601579 S2P_Cfg12_SW_Ver_Byte5_43 "CSC软件版本号Byte5对应的ASCII码(国产MCU)";
CM_ SG_ 2418601579 S2P_Cfg12_SW_Ver_Byte6_43 "CSC软件版本号Byte6对应的ASCII码(国产MCU)";
CM_ SG_ 2418601579 S2P_Cfg12_SW_Ver_Byte7_43 "CSC软件版本号Byte7对应的ASCII码(国产MCU)";
CM_ SG_ 2418601579 S2P_Cfg12_SW_Ver_Byte8_43 "CSC软件版本号Byte8对应的ASCII码(国产MCU)";
CM_ SG_ 2418601580 S2P_Cfg12_SW_Ver_Byte1_44 "CSC软件版本号最低字节Byte1对应的ASCII码(国产MCU)";
CM_ SG_ 2418601580 S2P_Cfg12_SW_Ver_Byte2_44 "CSC软件版本号Byte2对应的ASCII码(国产MCU)";
CM_ SG_ 2418601580 S2P_Cfg12_SW_Ver_Byte3_44 "CSC软件版本号Byte3对应的ASCII码(国产MCU)";
CM_ SG_ 2418601580 S2P_Cfg12_SW_Ver_Byte4_44 "CSC软件版本号Byte4对应的ASCII码(国产MCU)";
CM_ SG_ 2418601580 S2P_Cfg12_SW_Ver_Byte5_44 "CSC软件版本号Byte5对应的ASCII码(国产MCU)";
CM_ SG_ 2418601580 S2P_Cfg12_SW_Ver_Byte6_44 "CSC软件版本号Byte6对应的ASCII码(国产MCU)";
CM_ SG_ 2418601580 S2P_Cfg12_SW_Ver_Byte7_44 "CSC软件版本号Byte7对应的ASCII码(国产MCU)";
CM_ SG_ 2418601580 S2P_Cfg12_SW_Ver_Byte8_44 "CSC软件版本号Byte8对应的ASCII码(国产MCU)";
CM_ SG_ 2418601581 S2P_Cfg12_SW_Ver_Byte1_45 "CSC软件版本号最低字节Byte1对应的ASCII码(国产MCU)";
CM_ SG_ 2418601581 S2P_Cfg12_SW_Ver_Byte2_45 "CSC软件版本号Byte2对应的ASCII码(国产MCU)";
CM_ SG_ 2418601581 S2P_Cfg12_SW_Ver_Byte3_45 "CSC软件版本号Byte3对应的ASCII码(国产MCU)";
CM_ SG_ 2418601581 S2P_Cfg12_SW_Ver_Byte4_45 "CSC软件版本号Byte4对应的ASCII码(国产MCU)";
CM_ SG_ 2418601581 S2P_Cfg12_SW_Ver_Byte5_45 "CSC软件版本号Byte5对应的ASCII码(国产MCU)";
CM_ SG_ 2418601581 S2P_Cfg12_SW_Ver_Byte6_45 "CSC软件版本号Byte6对应的ASCII码(国产MCU)";
CM_ SG_ 2418601581 S2P_Cfg12_SW_Ver_Byte7_45 "CSC软件版本号Byte7对应的ASCII码(国产MCU)";
CM_ SG_ 2418601581 S2P_Cfg12_SW_Ver_Byte8_45 "CSC软件版本号Byte8对应的ASCII码(国产MCU)";
CM_ SG_ 2418601582 S2P_Cfg12_SW_Ver_Byte1_46 "CSC软件版本号最低字节Byte1对应的ASCII码(国产MCU)";
CM_ SG_ 2418601582 S2P_Cfg12_SW_Ver_Byte2_46 "CSC软件版本号Byte2对应的ASCII码(国产MCU)";
CM_ SG_ 2418601582 S2P_Cfg12_SW_Ver_Byte3_46 "CSC软件版本号Byte3对应的ASCII码(国产MCU)";
CM_ SG_ 2418601582 S2P_Cfg12_SW_Ver_Byte4_46 "CSC软件版本号Byte4对应的ASCII码(国产MCU)";
CM_ SG_ 2418601582 S2P_Cfg12_SW_Ver_Byte5_46 "CSC软件版本号Byte5对应的ASCII码(国产MCU)";
CM_ SG_ 2418601582 S2P_Cfg12_SW_Ver_Byte6_46 "CSC软件版本号Byte6对应的ASCII码(国产MCU)";
CM_ SG_ 2418601582 S2P_Cfg12_SW_Ver_Byte7_46 "CSC软件版本号Byte7对应的ASCII码(国产MCU)";
CM_ SG_ 2418601582 S2P_Cfg12_SW_Ver_Byte8_46 "CSC软件版本号Byte8对应的ASCII码(国产MCU)";
CM_ SG_ 2418601583 S2P_Cfg12_SW_Ver_Byte1_47 "CSC软件版本号最低字节Byte1对应的ASCII码(国产MCU)";
CM_ SG_ 2418601583 S2P_Cfg12_SW_Ver_Byte2_47 "CSC软件版本号Byte2对应的ASCII码(国产MCU)";
CM_ SG_ 2418601583 S2P_Cfg12_SW_Ver_Byte3_47 "CSC软件版本号Byte3对应的ASCII码(国产MCU)";
CM_ SG_ 2418601583 S2P_Cfg12_SW_Ver_Byte4_47 "CSC软件版本号Byte4对应的ASCII码(国产MCU)";
CM_ SG_ 2418601583 S2P_Cfg12_SW_Ver_Byte5_47 "CSC软件版本号Byte5对应的ASCII码(国产MCU)";
CM_ SG_ 2418601583 S2P_Cfg12_SW_Ver_Byte6_47 "CSC软件版本号Byte6对应的ASCII码(国产MCU)";
CM_ SG_ 2418601583 S2P_Cfg12_SW_Ver_Byte7_47 "CSC软件版本号Byte7对应的ASCII码(国产MCU)";
CM_ SG_ 2418601583 S2P_Cfg12_SW_Ver_Byte8_47 "CSC软件版本号Byte8对应的ASCII码(国产MCU)";
CM_ SG_ 2418601584 S2P_Cfg12_SW_Ver_Byte1_48 "CSC软件版本号最低字节Byte1对应的ASCII码(国产MCU)";
CM_ SG_ 2418601584 S2P_Cfg12_SW_Ver_Byte2_48 "CSC软件版本号Byte2对应的ASCII码(国产MCU)";
CM_ SG_ 2418601584 S2P_Cfg12_SW_Ver_Byte3_48 "CSC软件版本号Byte3对应的ASCII码(国产MCU)";
CM_ SG_ 2418601584 S2P_Cfg12_SW_Ver_Byte4_48 "CSC软件版本号Byte4对应的ASCII码(国产MCU)";
CM_ SG_ 2418601584 S2P_Cfg12_SW_Ver_Byte5_48 "CSC软件版本号Byte5对应的ASCII码(国产MCU)";
CM_ SG_ 2418601584 S2P_Cfg12_SW_Ver_Byte6_48 "CSC软件版本号Byte6对应的ASCII码(国产MCU)";
CM_ SG_ 2418601584 S2P_Cfg12_SW_Ver_Byte7_48 "CSC软件版本号Byte7对应的ASCII码(国产MCU)";
CM_ SG_ 2418601584 S2P_Cfg12_SW_Ver_Byte8_48 "CSC软件版本号Byte8对应的ASCII码(国产MCU)";
CM_ SG_ 2418601585 S2P_Cfg12_SW_Ver_Byte1_49 "CSC软件版本号最低字节Byte1对应的ASCII码(国产MCU)";
CM_ SG_ 2418601585 S2P_Cfg12_SW_Ver_Byte2_49 "CSC软件版本号Byte2对应的ASCII码(国产MCU)";
CM_ SG_ 2418601585 S2P_Cfg12_SW_Ver_Byte3_49 "CSC软件版本号Byte3对应的ASCII码(国产MCU)";
CM_ SG_ 2418601585 S2P_Cfg12_SW_Ver_Byte4_49 "CSC软件版本号Byte4对应的ASCII码(国产MCU)";
CM_ SG_ 2418601585 S2P_Cfg12_SW_Ver_Byte5_49 "CSC软件版本号Byte5对应的ASCII码(国产MCU)";
CM_ SG_ 2418601585 S2P_Cfg12_SW_Ver_Byte6_49 "CSC软件版本号Byte6对应的ASCII码(国产MCU)";
CM_ SG_ 2418601585 S2P_Cfg12_SW_Ver_Byte7_49 "CSC软件版本号Byte7对应的ASCII码(国产MCU)";
CM_ SG_ 2418601585 S2P_Cfg12_SW_Ver_Byte8_49 "CSC软件版本号Byte8对应的ASCII码(国产MCU)";
CM_ SG_ 2418601586 S2P_Cfg12_SW_Ver_Byte1_50 "CSC软件版本号最低字节Byte1对应的ASCII码(国产MCU)";
CM_ SG_ 2418601586 S2P_Cfg12_SW_Ver_Byte2_50 "CSC软件版本号Byte2对应的ASCII码(国产MCU)";
CM_ SG_ 2418601586 S2P_Cfg12_SW_Ver_Byte3_50 "CSC软件版本号Byte3对应的ASCII码(国产MCU)";
CM_ SG_ 2418601586 S2P_Cfg12_SW_Ver_Byte4_50 "CSC软件版本号Byte4对应的ASCII码(国产MCU)";
CM_ SG_ 2418601586 S2P_Cfg12_SW_Ver_Byte5_50 "CSC软件版本号Byte5对应的ASCII码(国产MCU)";
CM_ SG_ 2418601586 S2P_Cfg12_SW_Ver_Byte6_50 "CSC软件版本号Byte6对应的ASCII码(国产MCU)";
CM_ SG_ 2418601586 S2P_Cfg12_SW_Ver_Byte7_50 "CSC软件版本号Byte7对应的ASCII码(国产MCU)";
CM_ SG_ 2418601586 S2P_Cfg12_SW_Ver_Byte8_50 "CSC软件版本号Byte8对应的ASCII码(国产MCU)";
CM_ SG_ 2418601587 S2P_Cfg12_SW_Ver_Byte1_51 "CSC软件版本号最低字节Byte1对应的ASCII码(国产MCU)";
CM_ SG_ 2418601587 S2P_Cfg12_SW_Ver_Byte2_51 "CSC软件版本号Byte2对应的ASCII码(国产MCU)";
CM_ SG_ 2418601587 S2P_Cfg12_SW_Ver_Byte3_51 "CSC软件版本号Byte3对应的ASCII码(国产MCU)";
CM_ SG_ 2418601587 S2P_Cfg12_SW_Ver_Byte4_51 "CSC软件版本号Byte4对应的ASCII码(国产MCU)";
CM_ SG_ 2418601587 S2P_Cfg12_SW_Ver_Byte5_51 "CSC软件版本号Byte5对应的ASCII码(国产MCU)";
CM_ SG_ 2418601587 S2P_Cfg12_SW_Ver_Byte6_51 "CSC软件版本号Byte6对应的ASCII码(国产MCU)";
CM_ SG_ 2418601587 S2P_Cfg12_SW_Ver_Byte7_51 "CSC软件版本号Byte7对应的ASCII码(国产MCU)";
CM_ SG_ 2418601587 S2P_Cfg12_SW_Ver_Byte8_51 "CSC软件版本号Byte8对应的ASCII码(国产MCU)";
CM_ SG_ 2418601588 S2P_Cfg12_SW_Ver_Byte1_52 "CSC软件版本号最低字节Byte1对应的ASCII码(国产MCU)";
CM_ SG_ 2418601588 S2P_Cfg12_SW_Ver_Byte2_52 "CSC软件版本号Byte2对应的ASCII码(国产MCU)";
CM_ SG_ 2418601588 S2P_Cfg12_SW_Ver_Byte3_52 "CSC软件版本号Byte3对应的ASCII码(国产MCU)";
CM_ SG_ 2418601588 S2P_Cfg12_SW_Ver_Byte4_52 "CSC软件版本号Byte4对应的ASCII码(国产MCU)";
CM_ SG_ 2418601588 S2P_Cfg12_SW_Ver_Byte5_52 "CSC软件版本号Byte5对应的ASCII码(国产MCU)";
CM_ SG_ 2418601588 S2P_Cfg12_SW_Ver_Byte6_52 "CSC软件版本号Byte6对应的ASCII码(国产MCU)";
CM_ SG_ 2418601588 S2P_Cfg12_SW_Ver_Byte7_52 "CSC软件版本号Byte7对应的ASCII码(国产MCU)";
CM_ SG_ 2418601588 S2P_Cfg12_SW_Ver_Byte8_52 "CSC软件版本号Byte8对应的ASCII码(国产MCU)";
CM_ SG_ 2418601589 S2P_Cfg12_SW_Ver_Byte1_53 "CSC软件版本号最低字节Byte1对应的ASCII码(国产MCU)";
CM_ SG_ 2418601589 S2P_Cfg12_SW_Ver_Byte2_53 "CSC软件版本号Byte2对应的ASCII码(国产MCU)";
CM_ SG_ 2418601589 S2P_Cfg12_SW_Ver_Byte3_53 "CSC软件版本号Byte3对应的ASCII码(国产MCU)";
CM_ SG_ 2418601589 S2P_Cfg12_SW_Ver_Byte4_53 "CSC软件版本号Byte4对应的ASCII码(国产MCU)";
CM_ SG_ 2418601589 S2P_Cfg12_SW_Ver_Byte5_53 "CSC软件版本号Byte5对应的ASCII码(国产MCU)";
CM_ SG_ 2418601589 S2P_Cfg12_SW_Ver_Byte6_53 "CSC软件版本号Byte6对应的ASCII码(国产MCU)";
CM_ SG_ 2418601589 S2P_Cfg12_SW_Ver_Byte7_53 "CSC软件版本号Byte7对应的ASCII码(国产MCU)";
CM_ SG_ 2418601589 S2P_Cfg12_SW_Ver_Byte8_53 "CSC软件版本号Byte8对应的ASCII码(国产MCU)";
CM_ SG_ 2418601590 S2P_Cfg12_SW_Ver_Byte1_54 "CSC软件版本号最低字节Byte1对应的ASCII码(国产MCU)";
CM_ SG_ 2418601590 S2P_Cfg12_SW_Ver_Byte2_54 "CSC软件版本号Byte2对应的ASCII码(国产MCU)";
CM_ SG_ 2418601590 S2P_Cfg12_SW_Ver_Byte3_54 "CSC软件版本号Byte3对应的ASCII码(国产MCU)";
CM_ SG_ 2418601590 S2P_Cfg12_SW_Ver_Byte4_54 "CSC软件版本号Byte4对应的ASCII码(国产MCU)";
CM_ SG_ 2418601590 S2P_Cfg12_SW_Ver_Byte5_54 "CSC软件版本号Byte5对应的ASCII码(国产MCU)";
CM_ SG_ 2418601590 S2P_Cfg12_SW_Ver_Byte6_54 "CSC软件版本号Byte6对应的ASCII码(国产MCU)";
CM_ SG_ 2418601590 S2P_Cfg12_SW_Ver_Byte7_54 "CSC软件版本号Byte7对应的ASCII码(国产MCU)";
CM_ SG_ 2418601590 S2P_Cfg12_SW_Ver_Byte8_54 "CSC软件版本号Byte8对应的ASCII码(国产MCU)";
CM_ SG_ 2418601591 S2P_Cfg12_SW_Ver_Byte1_55 "CSC软件版本号最低字节Byte1对应的ASCII码(国产MCU)";
CM_ SG_ 2418601591 S2P_Cfg12_SW_Ver_Byte2_55 "CSC软件版本号Byte2对应的ASCII码(国产MCU)";
CM_ SG_ 2418601591 S2P_Cfg12_SW_Ver_Byte3_55 "CSC软件版本号Byte3对应的ASCII码(国产MCU)";
CM_ SG_ 2418601591 S2P_Cfg12_SW_Ver_Byte4_55 "CSC软件版本号Byte4对应的ASCII码(国产MCU)";
CM_ SG_ 2418601591 S2P_Cfg12_SW_Ver_Byte5_55 "CSC软件版本号Byte5对应的ASCII码(国产MCU)";
CM_ SG_ 2418601591 S2P_Cfg12_SW_Ver_Byte6_55 "CSC软件版本号Byte6对应的ASCII码(国产MCU)";
CM_ SG_ 2418601591 S2P_Cfg12_SW_Ver_Byte7_55 "CSC软件版本号Byte7对应的ASCII码(国产MCU)";
CM_ SG_ 2418601591 S2P_Cfg12_SW_Ver_Byte8_55 "CSC软件版本号Byte8对应的ASCII码(国产MCU)";
CM_ SG_ 2418601592 S2P_Cfg12_SW_Ver_Byte1_56 "CSC软件版本号最低字节Byte1对应的ASCII码(国产MCU)";
CM_ SG_ 2418601592 S2P_Cfg12_SW_Ver_Byte2_56 "CSC软件版本号Byte2对应的ASCII码(国产MCU)";
CM_ SG_ 2418601592 S2P_Cfg12_SW_Ver_Byte3_56 "CSC软件版本号Byte3对应的ASCII码(国产MCU)";
CM_ SG_ 2418601592 S2P_Cfg12_SW_Ver_Byte4_56 "CSC软件版本号Byte4对应的ASCII码(国产MCU)";
CM_ SG_ 2418601592 S2P_Cfg12_SW_Ver_Byte5_56 "CSC软件版本号Byte5对应的ASCII码(国产MCU)";
CM_ SG_ 2418601592 S2P_Cfg12_SW_Ver_Byte6_56 "CSC软件版本号Byte6对应的ASCII码(国产MCU)";
CM_ SG_ 2418601592 S2P_Cfg12_SW_Ver_Byte7_56 "CSC软件版本号Byte7对应的ASCII码(国产MCU)";
CM_ SG_ 2418601592 S2P_Cfg12_SW_Ver_Byte8_56 "CSC软件版本号Byte8对应的ASCII码(国产MCU)";
CM_ SG_ 2418601593 S2P_Cfg12_SW_Ver_Byte1_57 "CSC软件版本号最低字节Byte1对应的ASCII码(国产MCU)";
CM_ SG_ 2418601593 S2P_Cfg12_SW_Ver_Byte2_57 "CSC软件版本号Byte2对应的ASCII码(国产MCU)";
CM_ SG_ 2418601593 S2P_Cfg12_SW_Ver_Byte3_57 "CSC软件版本号Byte3对应的ASCII码(国产MCU)";
CM_ SG_ 2418601593 S2P_Cfg12_SW_Ver_Byte4_57 "CSC软件版本号Byte4对应的ASCII码(国产MCU)";
CM_ SG_ 2418601593 S2P_Cfg12_SW_Ver_Byte5_57 "CSC软件版本号Byte5对应的ASCII码(国产MCU)";
CM_ SG_ 2418601593 S2P_Cfg12_SW_Ver_Byte6_57 "CSC软件版本号Byte6对应的ASCII码(国产MCU)";
CM_ SG_ 2418601593 S2P_Cfg12_SW_Ver_Byte7_57 "CSC软件版本号Byte7对应的ASCII码(国产MCU)";
CM_ SG_ 2418601593 S2P_Cfg12_SW_Ver_Byte8_57 "CSC软件版本号Byte8对应的ASCII码(国产MCU)";
CM_ SG_ 2418601594 S2P_Cfg12_SW_Ver_Byte1_58 "CSC软件版本号最低字节Byte1对应的ASCII码(国产MCU)";
CM_ SG_ 2418601594 S2P_Cfg12_SW_Ver_Byte2_58 "CSC软件版本号Byte2对应的ASCII码(国产MCU)";
CM_ SG_ 2418601594 S2P_Cfg12_SW_Ver_Byte3_58 "CSC软件版本号Byte3对应的ASCII码(国产MCU)";
CM_ SG_ 2418601594 S2P_Cfg12_SW_Ver_Byte4_58 "CSC软件版本号Byte4对应的ASCII码(国产MCU)";
CM_ SG_ 2418601594 S2P_Cfg12_SW_Ver_Byte5_58 "CSC软件版本号Byte5对应的ASCII码(国产MCU)";
CM_ SG_ 2418601594 S2P_Cfg12_SW_Ver_Byte6_58 "CSC软件版本号Byte6对应的ASCII码(国产MCU)";
CM_ SG_ 2418601594 S2P_Cfg12_SW_Ver_Byte7_58 "CSC软件版本号Byte7对应的ASCII码(国产MCU)";
CM_ SG_ 2418601594 S2P_Cfg12_SW_Ver_Byte8_58 "CSC软件版本号Byte8对应的ASCII码(国产MCU)";
CM_ SG_ 2418601595 S2P_Cfg12_SW_Ver_Byte1_59 "CSC软件版本号最低字节Byte1对应的ASCII码(国产MCU)";
CM_ SG_ 2418601595 S2P_Cfg12_SW_Ver_Byte2_59 "CSC软件版本号Byte2对应的ASCII码(国产MCU)";
CM_ SG_ 2418601595 S2P_Cfg12_SW_Ver_Byte3_59 "CSC软件版本号Byte3对应的ASCII码(国产MCU)";
CM_ SG_ 2418601595 S2P_Cfg12_SW_Ver_Byte4_59 "CSC软件版本号Byte4对应的ASCII码(国产MCU)";
CM_ SG_ 2418601595 S2P_Cfg12_SW_Ver_Byte5_59 "CSC软件版本号Byte5对应的ASCII码(国产MCU)";
CM_ SG_ 2418601595 S2P_Cfg12_SW_Ver_Byte6_59 "CSC软件版本号Byte6对应的ASCII码(国产MCU)";
CM_ SG_ 2418601595 S2P_Cfg12_SW_Ver_Byte7_59 "CSC软件版本号Byte7对应的ASCII码(国产MCU)";
CM_ SG_ 2418601595 S2P_Cfg12_SW_Ver_Byte8_59 "CSC软件版本号Byte8对应的ASCII码(国产MCU)";
CM_ SG_ 2418601596 S2P_Cfg12_SW_Ver_Byte1_60 "CSC软件版本号最低字节Byte1对应的ASCII码(国产MCU)";
CM_ SG_ 2418601596 S2P_Cfg12_SW_Ver_Byte2_60 "CSC软件版本号Byte2对应的ASCII码(国产MCU)";
CM_ SG_ 2418601596 S2P_Cfg12_SW_Ver_Byte3_60 "CSC软件版本号Byte3对应的ASCII码(国产MCU)";
CM_ SG_ 2418601596 S2P_Cfg12_SW_Ver_Byte4_60 "CSC软件版本号Byte4对应的ASCII码(国产MCU)";
CM_ SG_ 2418601596 S2P_Cfg12_SW_Ver_Byte5_60 "CSC软件版本号Byte5对应的ASCII码(国产MCU)";
CM_ SG_ 2418601596 S2P_Cfg12_SW_Ver_Byte6_60 "CSC软件版本号Byte6对应的ASCII码(国产MCU)";
CM_ SG_ 2418601596 S2P_Cfg12_SW_Ver_Byte7_60 "CSC软件版本号Byte7对应的ASCII码(国产MCU)";
CM_ SG_ 2418601596 S2P_Cfg12_SW_Ver_Byte8_60 "CSC软件版本号Byte8对应的ASCII码(国产MCU)";
CM_ SG_ 2418601597 S2P_Cfg12_SW_Ver_Byte1_61 "CSC软件版本号最低字节Byte1对应的ASCII码(国产MCU)";
CM_ SG_ 2418601597 S2P_Cfg12_SW_Ver_Byte2_61 "CSC软件版本号Byte2对应的ASCII码(国产MCU)";
CM_ SG_ 2418601597 S2P_Cfg12_SW_Ver_Byte3_61 "CSC软件版本号Byte3对应的ASCII码(国产MCU)";
CM_ SG_ 2418601597 S2P_Cfg12_SW_Ver_Byte4_61 "CSC软件版本号Byte4对应的ASCII码(国产MCU)";
CM_ SG_ 2418601597 S2P_Cfg12_SW_Ver_Byte5_61 "CSC软件版本号Byte5对应的ASCII码(国产MCU)";
CM_ SG_ 2418601597 S2P_Cfg12_SW_Ver_Byte6_61 "CSC软件版本号Byte6对应的ASCII码(国产MCU)";
CM_ SG_ 2418601597 S2P_Cfg12_SW_Ver_Byte7_61 "CSC软件版本号Byte7对应的ASCII码(国产MCU)";
CM_ SG_ 2418601597 S2P_Cfg12_SW_Ver_Byte8_61 "CSC软件版本号Byte8对应的ASCII码(国产MCU)";
CM_ SG_ 2418601598 S2P_Cfg12_SW_Ver_Byte1_62 "CSC软件版本号最低字节Byte1对应的ASCII码(国产MCU)";
CM_ SG_ 2418601598 S2P_Cfg12_SW_Ver_Byte2_62 "CSC软件版本号Byte2对应的ASCII码(国产MCU)";
CM_ SG_ 2418601598 S2P_Cfg12_SW_Ver_Byte3_62 "CSC软件版本号Byte3对应的ASCII码(国产MCU)";
CM_ SG_ 2418601598 S2P_Cfg12_SW_Ver_Byte4_62 "CSC软件版本号Byte4对应的ASCII码(国产MCU)";
CM_ SG_ 2418601598 S2P_Cfg12_SW_Ver_Byte5_62 "CSC软件版本号Byte5对应的ASCII码(国产MCU)";
CM_ SG_ 2418601598 S2P_Cfg12_SW_Ver_Byte6_62 "CSC软件版本号Byte6对应的ASCII码(国产MCU)";
CM_ SG_ 2418601598 S2P_Cfg12_SW_Ver_Byte7_62 "CSC软件版本号Byte7对应的ASCII码(国产MCU)";
CM_ SG_ 2418601598 S2P_Cfg12_SW_Ver_Byte8_62 "CSC软件版本号Byte8对应的ASCII码(国产MCU)";
CM_ SG_ 2418601599 S2P_Cfg12_SW_Ver_Byte1_63 "CSC软件版本号最低字节Byte1对应的ASCII码(国产MCU)";
CM_ SG_ 2418601599 S2P_Cfg12_SW_Ver_Byte2_63 "CSC软件版本号Byte2对应的ASCII码(国产MCU)";
CM_ SG_ 2418601599 S2P_Cfg12_SW_Ver_Byte3_63 "CSC软件版本号Byte3对应的ASCII码(国产MCU)";
CM_ SG_ 2418601599 S2P_Cfg12_SW_Ver_Byte4_63 "CSC软件版本号Byte4对应的ASCII码(国产MCU)";
CM_ SG_ 2418601599 S2P_Cfg12_SW_Ver_Byte5_63 "CSC软件版本号Byte5对应的ASCII码(国产MCU)";
CM_ SG_ 2418601599 S2P_Cfg12_SW_Ver_Byte6_63 "CSC软件版本号Byte6对应的ASCII码(国产MCU)";
CM_ SG_ 2418601599 S2P_Cfg12_SW_Ver_Byte7_63 "CSC软件版本号Byte7对应的ASCII码(国产MCU)";
CM_ SG_ 2418601599 S2P_Cfg12_SW_Ver_Byte8_63 "CSC软件版本号Byte8对应的ASCII码(国产MCU)";
CM_ SG_ 2418667073 S2P_Cfg13_SW_Ver_Byte9_01 "CSC软件版本号Byte9对应的ASCII码(国产MCU)";
CM_ SG_ 2418667073 S2P_Cfg13_SW_Ver_Byte10_01 "CSC软件版本号Byte10对应的ASCII码(国产MCU)";
CM_ SG_ 2418667073 S2P_Cfg13_SW_Ver_Byte11_01 "CSC软件版本号Byte11对应的ASCII码(国产MCU)";
CM_ SG_ 2418667073 S2P_Cfg13_SW_Ver_Byte12_01 "CSC软件版本号Byte12对应的ASCII码(国产MCU)";
CM_ SG_ 2418667073 S2P_Cfg13_SW_Ver_Byte13_01 "CSC软件版本号Byte13对应的ASCII码(国产MCU)";
CM_ SG_ 2418667073 S2P_Cfg13_SW_Ver_Byte14_01 "CSC软件版本号Byte14对应的ASCII码(国产MCU)";
CM_ SG_ 2418667073 S2P_Cfg13_SW_Ver_Byte15_01 "CSC软件版本号Byte15对应的ASCII码(国产MCU)";
CM_ SG_ 2418667073 S2P_Cfg13_SW_Ver_Byte16_01 "CSC软件版本号最高字节Byte16对应的ASCII码(国产MCU)";
CM_ SG_ 2418667074 S2P_Cfg13_SW_Ver_Byte9_02 "CSC软件版本号Byte9对应的ASCII码(国产MCU)";
CM_ SG_ 2418667074 S2P_Cfg13_SW_Ver_Byte10_02 "CSC软件版本号Byte10对应的ASCII码(国产MCU)";
CM_ SG_ 2418667074 S2P_Cfg13_SW_Ver_Byte11_02 "CSC软件版本号Byte11对应的ASCII码(国产MCU)";
CM_ SG_ 2418667074 S2P_Cfg13_SW_Ver_Byte12_02 "CSC软件版本号Byte12对应的ASCII码(国产MCU)";
CM_ SG_ 2418667074 S2P_Cfg13_SW_Ver_Byte13_02 "CSC软件版本号Byte13对应的ASCII码(国产MCU)";
CM_ SG_ 2418667074 S2P_Cfg13_SW_Ver_Byte14_02 "CSC软件版本号Byte14对应的ASCII码(国产MCU)";
CM_ SG_ 2418667074 S2P_Cfg13_SW_Ver_Byte15_02 "CSC软件版本号Byte15对应的ASCII码(国产MCU)";
CM_ SG_ 2418667074 S2P_Cfg13_SW_Ver_Byte16_02 "CSC软件版本号最高字节Byte16对应的ASCII码(国产MCU)";
CM_ SG_ 2418667075 S2P_Cfg13_SW_Ver_Byte9_03 "CSC软件版本号Byte9对应的ASCII码(国产MCU)";
CM_ SG_ 2418667075 S2P_Cfg13_SW_Ver_Byte10_03 "CSC软件版本号Byte10对应的ASCII码(国产MCU)";
CM_ SG_ 2418667075 S2P_Cfg13_SW_Ver_Byte11_03 "CSC软件版本号Byte11对应的ASCII码(国产MCU)";
CM_ SG_ 2418667075 S2P_Cfg13_SW_Ver_Byte12_03 "CSC软件版本号Byte12对应的ASCII码(国产MCU)";
CM_ SG_ 2418667075 S2P_Cfg13_SW_Ver_Byte13_03 "CSC软件版本号Byte13对应的ASCII码(国产MCU)";
CM_ SG_ 2418667075 S2P_Cfg13_SW_Ver_Byte14_03 "CSC软件版本号Byte14对应的ASCII码(国产MCU)";
CM_ SG_ 2418667075 S2P_Cfg13_SW_Ver_Byte15_03 "CSC软件版本号Byte15对应的ASCII码(国产MCU)";
CM_ SG_ 2418667075 S2P_Cfg13_SW_Ver_Byte16_03 "CSC软件版本号最高字节Byte16对应的ASCII码(国产MCU)";
CM_ SG_ 2418667076 S2P_Cfg13_SW_Ver_Byte9_04 "CSC软件版本号Byte9对应的ASCII码(国产MCU)";
CM_ SG_ 2418667076 S2P_Cfg13_SW_Ver_Byte10_04 "CSC软件版本号Byte10对应的ASCII码(国产MCU)";
CM_ SG_ 2418667076 S2P_Cfg13_SW_Ver_Byte11_04 "CSC软件版本号Byte11对应的ASCII码(国产MCU)";
CM_ SG_ 2418667076 S2P_Cfg13_SW_Ver_Byte12_04 "CSC软件版本号Byte12对应的ASCII码(国产MCU)";
CM_ SG_ 2418667076 S2P_Cfg13_SW_Ver_Byte13_04 "CSC软件版本号Byte13对应的ASCII码(国产MCU)";
CM_ SG_ 2418667076 S2P_Cfg13_SW_Ver_Byte14_04 "CSC软件版本号Byte14对应的ASCII码(国产MCU)";
CM_ SG_ 2418667076 S2P_Cfg13_SW_Ver_Byte15_04 "CSC软件版本号Byte15对应的ASCII码(国产MCU)";
CM_ SG_ 2418667076 S2P_Cfg13_SW_Ver_Byte16_04 "CSC软件版本号最高字节Byte16对应的ASCII码(国产MCU)";
CM_ SG_ 2418667077 S2P_Cfg13_SW_Ver_Byte9_05 "CSC软件版本号Byte9对应的ASCII码(国产MCU)";
CM_ SG_ 2418667077 S2P_Cfg13_SW_Ver_Byte10_05 "CSC软件版本号Byte10对应的ASCII码(国产MCU)";
CM_ SG_ 2418667077 S2P_Cfg13_SW_Ver_Byte11_05 "CSC软件版本号Byte11对应的ASCII码(国产MCU)";
CM_ SG_ 2418667077 S2P_Cfg13_SW_Ver_Byte12_05 "CSC软件版本号Byte12对应的ASCII码(国产MCU)";
CM_ SG_ 2418667077 S2P_Cfg13_SW_Ver_Byte13_05 "CSC软件版本号Byte13对应的ASCII码(国产MCU)";
CM_ SG_ 2418667077 S2P_Cfg13_SW_Ver_Byte14_05 "CSC软件版本号Byte14对应的ASCII码(国产MCU)";
CM_ SG_ 2418667077 S2P_Cfg13_SW_Ver_Byte15_05 "CSC软件版本号Byte15对应的ASCII码(国产MCU)";
CM_ SG_ 2418667077 S2P_Cfg13_SW_Ver_Byte16_05 "CSC软件版本号最高字节Byte16对应的ASCII码(国产MCU)";
CM_ SG_ 2418667078 S2P_Cfg13_SW_Ver_Byte9_06 "CSC软件版本号Byte9对应的ASCII码(国产MCU)";
CM_ SG_ 2418667078 S2P_Cfg13_SW_Ver_Byte10_06 "CSC软件版本号Byte10对应的ASCII码(国产MCU)";
CM_ SG_ 2418667078 S2P_Cfg13_SW_Ver_Byte11_06 "CSC软件版本号Byte11对应的ASCII码(国产MCU)";
CM_ SG_ 2418667078 S2P_Cfg13_SW_Ver_Byte12_06 "CSC软件版本号Byte12对应的ASCII码(国产MCU)";
CM_ SG_ 2418667078 S2P_Cfg13_SW_Ver_Byte13_06 "CSC软件版本号Byte13对应的ASCII码(国产MCU)";
CM_ SG_ 2418667078 S2P_Cfg13_SW_Ver_Byte14_06 "CSC软件版本号Byte14对应的ASCII码(国产MCU)";
CM_ SG_ 2418667078 S2P_Cfg13_SW_Ver_Byte15_06 "CSC软件版本号Byte15对应的ASCII码(国产MCU)";
CM_ SG_ 2418667078 S2P_Cfg13_SW_Ver_Byte16_06 "CSC软件版本号最高字节Byte16对应的ASCII码(国产MCU)";
CM_ SG_ 2418667079 S2P_Cfg13_SW_Ver_Byte9_07 "CSC软件版本号Byte9对应的ASCII码(国产MCU)";
CM_ SG_ 2418667079 S2P_Cfg13_SW_Ver_Byte10_07 "CSC软件版本号Byte10对应的ASCII码(国产MCU)";
CM_ SG_ 2418667079 S2P_Cfg13_SW_Ver_Byte11_07 "CSC软件版本号Byte11对应的ASCII码(国产MCU)";
CM_ SG_ 2418667079 S2P_Cfg13_SW_Ver_Byte12_07 "CSC软件版本号Byte12对应的ASCII码(国产MCU)";
CM_ SG_ 2418667079 S2P_Cfg13_SW_Ver_Byte13_07 "CSC软件版本号Byte13对应的ASCII码(国产MCU)";
CM_ SG_ 2418667079 S2P_Cfg13_SW_Ver_Byte14_07 "CSC软件版本号Byte14对应的ASCII码(国产MCU)";
CM_ SG_ 2418667079 S2P_Cfg13_SW_Ver_Byte15_07 "CSC软件版本号Byte15对应的ASCII码(国产MCU)";
CM_ SG_ 2418667079 S2P_Cfg13_SW_Ver_Byte16_07 "CSC软件版本号最高字节Byte16对应的ASCII码(国产MCU)";
CM_ SG_ 2418667080 S2P_Cfg13_SW_Ver_Byte9_08 "CSC软件版本号Byte9对应的ASCII码(国产MCU)";
CM_ SG_ 2418667080 S2P_Cfg13_SW_Ver_Byte10_08 "CSC软件版本号Byte10对应的ASCII码(国产MCU)";
CM_ SG_ 2418667080 S2P_Cfg13_SW_Ver_Byte11_08 "CSC软件版本号Byte11对应的ASCII码(国产MCU)";
CM_ SG_ 2418667080 S2P_Cfg13_SW_Ver_Byte12_08 "CSC软件版本号Byte12对应的ASCII码(国产MCU)";
CM_ SG_ 2418667080 S2P_Cfg13_SW_Ver_Byte13_08 "CSC软件版本号Byte13对应的ASCII码(国产MCU)";
CM_ SG_ 2418667080 S2P_Cfg13_SW_Ver_Byte14_08 "CSC软件版本号Byte14对应的ASCII码(国产MCU)";
CM_ SG_ 2418667080 S2P_Cfg13_SW_Ver_Byte15_08 "CSC软件版本号Byte15对应的ASCII码(国产MCU)";
CM_ SG_ 2418667080 S2P_Cfg13_SW_Ver_Byte16_08 "CSC软件版本号最高字节Byte16对应的ASCII码(国产MCU)";
CM_ SG_ 2418667081 S2P_Cfg13_SW_Ver_Byte9_09 "CSC软件版本号Byte9对应的ASCII码(国产MCU)";
CM_ SG_ 2418667081 S2P_Cfg13_SW_Ver_Byte10_09 "CSC软件版本号Byte10对应的ASCII码(国产MCU)";
CM_ SG_ 2418667081 S2P_Cfg13_SW_Ver_Byte11_09 "CSC软件版本号Byte11对应的ASCII码(国产MCU)";
CM_ SG_ 2418667081 S2P_Cfg13_SW_Ver_Byte12_09 "CSC软件版本号Byte12对应的ASCII码(国产MCU)";
CM_ SG_ 2418667081 S2P_Cfg13_SW_Ver_Byte13_09 "CSC软件版本号Byte13对应的ASCII码(国产MCU)";
CM_ SG_ 2418667081 S2P_Cfg13_SW_Ver_Byte14_09 "CSC软件版本号Byte14对应的ASCII码(国产MCU)";
CM_ SG_ 2418667081 S2P_Cfg13_SW_Ver_Byte15_09 "CSC软件版本号Byte15对应的ASCII码(国产MCU)";
CM_ SG_ 2418667081 S2P_Cfg13_SW_Ver_Byte16_09 "CSC软件版本号最高字节Byte16对应的ASCII码(国产MCU)";
CM_ SG_ 2418667082 S2P_Cfg13_SW_Ver_Byte9_10 "CSC软件版本号Byte9对应的ASCII码(国产MCU)";
CM_ SG_ 2418667082 S2P_Cfg13_SW_Ver_Byte10_10 "CSC软件版本号Byte10对应的ASCII码(国产MCU)";
CM_ SG_ 2418667082 S2P_Cfg13_SW_Ver_Byte11_10 "CSC软件版本号Byte11对应的ASCII码(国产MCU)";
CM_ SG_ 2418667082 S2P_Cfg13_SW_Ver_Byte12_10 "CSC软件版本号Byte12对应的ASCII码(国产MCU)";
CM_ SG_ 2418667082 S2P_Cfg13_SW_Ver_Byte13_10 "CSC软件版本号Byte13对应的ASCII码(国产MCU)";
CM_ SG_ 2418667082 S2P_Cfg13_SW_Ver_Byte14_10 "CSC软件版本号Byte14对应的ASCII码(国产MCU)";
CM_ SG_ 2418667082 S2P_Cfg13_SW_Ver_Byte15_10 "CSC软件版本号Byte15对应的ASCII码(国产MCU)";
CM_ SG_ 2418667082 S2P_Cfg13_SW_Ver_Byte16_10 "CSC软件版本号最高字节Byte16对应的ASCII码(国产MCU)";
CM_ SG_ 2418667083 S2P_Cfg13_SW_Ver_Byte9_11 "CSC软件版本号Byte9对应的ASCII码(国产MCU)";
CM_ SG_ 2418667083 S2P_Cfg13_SW_Ver_Byte10_11 "CSC软件版本号Byte10对应的ASCII码(国产MCU)";
CM_ SG_ 2418667083 S2P_Cfg13_SW_Ver_Byte11_11 "CSC软件版本号Byte11对应的ASCII码(国产MCU)";
CM_ SG_ 2418667083 S2P_Cfg13_SW_Ver_Byte12_11 "CSC软件版本号Byte12对应的ASCII码(国产MCU)";
CM_ SG_ 2418667083 S2P_Cfg13_SW_Ver_Byte13_11 "CSC软件版本号Byte13对应的ASCII码(国产MCU)";
CM_ SG_ 2418667083 S2P_Cfg13_SW_Ver_Byte14_11 "CSC软件版本号Byte14对应的ASCII码(国产MCU)";
CM_ SG_ 2418667083 S2P_Cfg13_SW_Ver_Byte15_11 "CSC软件版本号Byte15对应的ASCII码(国产MCU)";
CM_ SG_ 2418667083 S2P_Cfg13_SW_Ver_Byte16_11 "CSC软件版本号最高字节Byte16对应的ASCII码(国产MCU)";
CM_ SG_ 2418667084 S2P_Cfg13_SW_Ver_Byte9_12 "CSC软件版本号Byte9对应的ASCII码(国产MCU)";
CM_ SG_ 2418667084 S2P_Cfg13_SW_Ver_Byte10_12 "CSC软件版本号Byte10对应的ASCII码(国产MCU)";
CM_ SG_ 2418667084 S2P_Cfg13_SW_Ver_Byte11_12 "CSC软件版本号Byte11对应的ASCII码(国产MCU)";
CM_ SG_ 2418667084 S2P_Cfg13_SW_Ver_Byte12_12 "CSC软件版本号Byte12对应的ASCII码(国产MCU)";
CM_ SG_ 2418667084 S2P_Cfg13_SW_Ver_Byte13_12 "CSC软件版本号Byte13对应的ASCII码(国产MCU)";
CM_ SG_ 2418667084 S2P_Cfg13_SW_Ver_Byte14_12 "CSC软件版本号Byte14对应的ASCII码(国产MCU)";
CM_ SG_ 2418667084 S2P_Cfg13_SW_Ver_Byte15_12 "CSC软件版本号Byte15对应的ASCII码(国产MCU)";
CM_ SG_ 2418667084 S2P_Cfg13_SW_Ver_Byte16_12 "CSC软件版本号最高字节Byte16对应的ASCII码(国产MCU)";
CM_ SG_ 2418667085 S2P_Cfg13_SW_Ver_Byte9_13 "CSC软件版本号Byte9对应的ASCII码(国产MCU)";
CM_ SG_ 2418667085 S2P_Cfg13_SW_Ver_Byte10_13 "CSC软件版本号Byte10对应的ASCII码(国产MCU)";
CM_ SG_ 2418667085 S2P_Cfg13_SW_Ver_Byte11_13 "CSC软件版本号Byte11对应的ASCII码(国产MCU)";
CM_ SG_ 2418667085 S2P_Cfg13_SW_Ver_Byte12_13 "CSC软件版本号Byte12对应的ASCII码(国产MCU)";
CM_ SG_ 2418667085 S2P_Cfg13_SW_Ver_Byte13_13 "CSC软件版本号Byte13对应的ASCII码(国产MCU)";
CM_ SG_ 2418667085 S2P_Cfg13_SW_Ver_Byte14_13 "CSC软件版本号Byte14对应的ASCII码(国产MCU)";
CM_ SG_ 2418667085 S2P_Cfg13_SW_Ver_Byte15_13 "CSC软件版本号Byte15对应的ASCII码(国产MCU)";
CM_ SG_ 2418667085 S2P_Cfg13_SW_Ver_Byte16_13 "CSC软件版本号最高字节Byte16对应的ASCII码(国产MCU)";
CM_ SG_ 2418667086 S2P_Cfg13_SW_Ver_Byte9_14 "CSC软件版本号Byte9对应的ASCII码(国产MCU)";
CM_ SG_ 2418667086 S2P_Cfg13_SW_Ver_Byte10_14 "CSC软件版本号Byte10对应的ASCII码(国产MCU)";
CM_ SG_ 2418667086 S2P_Cfg13_SW_Ver_Byte11_14 "CSC软件版本号Byte11对应的ASCII码(国产MCU)";
CM_ SG_ 2418667086 S2P_Cfg13_SW_Ver_Byte12_14 "CSC软件版本号Byte12对应的ASCII码(国产MCU)";
CM_ SG_ 2418667086 S2P_Cfg13_SW_Ver_Byte13_14 "CSC软件版本号Byte13对应的ASCII码(国产MCU)";
CM_ SG_ 2418667086 S2P_Cfg13_SW_Ver_Byte14_14 "CSC软件版本号Byte14对应的ASCII码(国产MCU)";
CM_ SG_ 2418667086 S2P_Cfg13_SW_Ver_Byte15_14 "CSC软件版本号Byte15对应的ASCII码(国产MCU)";
CM_ SG_ 2418667086 S2P_Cfg13_SW_Ver_Byte16_14 "CSC软件版本号最高字节Byte16对应的ASCII码(国产MCU)";
CM_ SG_ 2418667087 S2P_Cfg13_SW_Ver_Byte9_15 "CSC软件版本号Byte9对应的ASCII码(国产MCU)";
CM_ SG_ 2418667087 S2P_Cfg13_SW_Ver_Byte10_15 "CSC软件版本号Byte10对应的ASCII码(国产MCU)";
CM_ SG_ 2418667087 S2P_Cfg13_SW_Ver_Byte11_15 "CSC软件版本号Byte11对应的ASCII码(国产MCU)";
CM_ SG_ 2418667087 S2P_Cfg13_SW_Ver_Byte12_15 "CSC软件版本号Byte12对应的ASCII码(国产MCU)";
CM_ SG_ 2418667087 S2P_Cfg13_SW_Ver_Byte13_15 "CSC软件版本号Byte13对应的ASCII码(国产MCU)";
CM_ SG_ 2418667087 S2P_Cfg13_SW_Ver_Byte14_15 "CSC软件版本号Byte14对应的ASCII码(国产MCU)";
CM_ SG_ 2418667087 S2P_Cfg13_SW_Ver_Byte15_15 "CSC软件版本号Byte15对应的ASCII码(国产MCU)";
CM_ SG_ 2418667087 S2P_Cfg13_SW_Ver_Byte16_15 "CSC软件版本号最高字节Byte16对应的ASCII码(国产MCU)";
CM_ SG_ 2418667088 S2P_Cfg13_SW_Ver_Byte9_16 "CSC软件版本号Byte9对应的ASCII码(国产MCU)";
CM_ SG_ 2418667088 S2P_Cfg13_SW_Ver_Byte10_16 "CSC软件版本号Byte10对应的ASCII码(国产MCU)";
CM_ SG_ 2418667088 S2P_Cfg13_SW_Ver_Byte11_16 "CSC软件版本号Byte11对应的ASCII码(国产MCU)";
CM_ SG_ 2418667088 S2P_Cfg13_SW_Ver_Byte12_16 "CSC软件版本号Byte12对应的ASCII码(国产MCU)";
CM_ SG_ 2418667088 S2P_Cfg13_SW_Ver_Byte13_16 "CSC软件版本号Byte13对应的ASCII码(国产MCU)";
CM_ SG_ 2418667088 S2P_Cfg13_SW_Ver_Byte14_16 "CSC软件版本号Byte14对应的ASCII码(国产MCU)";
CM_ SG_ 2418667088 S2P_Cfg13_SW_Ver_Byte15_16 "CSC软件版本号Byte15对应的ASCII码(国产MCU)";
CM_ SG_ 2418667088 S2P_Cfg13_SW_Ver_Byte16_16 "CSC软件版本号最高字节Byte16对应的ASCII码(国产MCU)";
CM_ SG_ 2418667089 S2P_Cfg13_SW_Ver_Byte9_17 "CSC软件版本号Byte9对应的ASCII码(国产MCU)";
CM_ SG_ 2418667089 S2P_Cfg13_SW_Ver_Byte10_17 "CSC软件版本号Byte10对应的ASCII码(国产MCU)";
CM_ SG_ 2418667089 S2P_Cfg13_SW_Ver_Byte11_17 "CSC软件版本号Byte11对应的ASCII码(国产MCU)";
CM_ SG_ 2418667089 S2P_Cfg13_SW_Ver_Byte12_17 "CSC软件版本号Byte12对应的ASCII码(国产MCU)";
CM_ SG_ 2418667089 S2P_Cfg13_SW_Ver_Byte13_17 "CSC软件版本号Byte13对应的ASCII码(国产MCU)";
CM_ SG_ 2418667089 S2P_Cfg13_SW_Ver_Byte14_17 "CSC软件版本号Byte14对应的ASCII码(国产MCU)";
CM_ SG_ 2418667089 S2P_Cfg13_SW_Ver_Byte15_17 "CSC软件版本号Byte15对应的ASCII码(国产MCU)";
CM_ SG_ 2418667089 S2P_Cfg13_SW_Ver_Byte16_17 "CSC软件版本号最高字节Byte16对应的ASCII码(国产MCU)";
CM_ SG_ 2418667090 S2P_Cfg13_SW_Ver_Byte9_18 "CSC软件版本号Byte9对应的ASCII码(国产MCU)";
CM_ SG_ 2418667090 S2P_Cfg13_SW_Ver_Byte10_18 "CSC软件版本号Byte10对应的ASCII码(国产MCU)";
CM_ SG_ 2418667090 S2P_Cfg13_SW_Ver_Byte11_18 "CSC软件版本号Byte11对应的ASCII码(国产MCU)";
CM_ SG_ 2418667090 S2P_Cfg13_SW_Ver_Byte12_18 "CSC软件版本号Byte12对应的ASCII码(国产MCU)";
CM_ SG_ 2418667090 S2P_Cfg13_SW_Ver_Byte13_18 "CSC软件版本号Byte13对应的ASCII码(国产MCU)";
CM_ SG_ 2418667090 S2P_Cfg13_SW_Ver_Byte14_18 "CSC软件版本号Byte14对应的ASCII码(国产MCU)";
CM_ SG_ 2418667090 S2P_Cfg13_SW_Ver_Byte15_18 "CSC软件版本号Byte15对应的ASCII码(国产MCU)";
CM_ SG_ 2418667090 S2P_Cfg13_SW_Ver_Byte16_18 "CSC软件版本号最高字节Byte16对应的ASCII码(国产MCU)";
CM_ SG_ 2418667091 S2P_Cfg13_SW_Ver_Byte9_19 "CSC软件版本号Byte9对应的ASCII码(国产MCU)";
CM_ SG_ 2418667091 S2P_Cfg13_SW_Ver_Byte10_19 "CSC软件版本号Byte10对应的ASCII码(国产MCU)";
CM_ SG_ 2418667091 S2P_Cfg13_SW_Ver_Byte11_19 "CSC软件版本号Byte11对应的ASCII码(国产MCU)";
CM_ SG_ 2418667091 S2P_Cfg13_SW_Ver_Byte12_19 "CSC软件版本号Byte12对应的ASCII码(国产MCU)";
CM_ SG_ 2418667091 S2P_Cfg13_SW_Ver_Byte13_19 "CSC软件版本号Byte13对应的ASCII码(国产MCU)";
CM_ SG_ 2418667091 S2P_Cfg13_SW_Ver_Byte14_19 "CSC软件版本号Byte14对应的ASCII码(国产MCU)";
CM_ SG_ 2418667091 S2P_Cfg13_SW_Ver_Byte15_19 "CSC软件版本号Byte15对应的ASCII码(国产MCU)";
CM_ SG_ 2418667091 S2P_Cfg13_SW_Ver_Byte16_19 "CSC软件版本号最高字节Byte16对应的ASCII码(国产MCU)";
CM_ SG_ 2418667092 S2P_Cfg13_SW_Ver_Byte9_20 "CSC软件版本号Byte9对应的ASCII码(国产MCU)";
CM_ SG_ 2418667092 S2P_Cfg13_SW_Ver_Byte10_20 "CSC软件版本号Byte10对应的ASCII码(国产MCU)";
CM_ SG_ 2418667092 S2P_Cfg13_SW_Ver_Byte11_20 "CSC软件版本号Byte11对应的ASCII码(国产MCU)";
CM_ SG_ 2418667092 S2P_Cfg13_SW_Ver_Byte12_20 "CSC软件版本号Byte12对应的ASCII码(国产MCU)";
CM_ SG_ 2418667092 S2P_Cfg13_SW_Ver_Byte13_20 "CSC软件版本号Byte13对应的ASCII码(国产MCU)";
CM_ SG_ 2418667092 S2P_Cfg13_SW_Ver_Byte14_20 "CSC软件版本号Byte14对应的ASCII码(国产MCU)";
CM_ SG_ 2418667092 S2P_Cfg13_SW_Ver_Byte15_20 "CSC软件版本号Byte15对应的ASCII码(国产MCU)";
CM_ SG_ 2418667092 S2P_Cfg13_SW_Ver_Byte16_20 "CSC软件版本号最高字节Byte16对应的ASCII码(国产MCU)";
CM_ SG_ 2418667093 S2P_Cfg13_SW_Ver_Byte9_21 "CSC软件版本号Byte9对应的ASCII码(国产MCU)";
CM_ SG_ 2418667093 S2P_Cfg13_SW_Ver_Byte10_21 "CSC软件版本号Byte10对应的ASCII码(国产MCU)";
CM_ SG_ 2418667093 S2P_Cfg13_SW_Ver_Byte11_21 "CSC软件版本号Byte11对应的ASCII码(国产MCU)";
CM_ SG_ 2418667093 S2P_Cfg13_SW_Ver_Byte12_21 "CSC软件版本号Byte12对应的ASCII码(国产MCU)";
CM_ SG_ 2418667093 S2P_Cfg13_SW_Ver_Byte13_21 "CSC软件版本号Byte13对应的ASCII码(国产MCU)";
CM_ SG_ 2418667093 S2P_Cfg13_SW_Ver_Byte14_21 "CSC软件版本号Byte14对应的ASCII码(国产MCU)";
CM_ SG_ 2418667093 S2P_Cfg13_SW_Ver_Byte15_21 "CSC软件版本号Byte15对应的ASCII码(国产MCU)";
CM_ SG_ 2418667093 S2P_Cfg13_SW_Ver_Byte16_21 "CSC软件版本号最高字节Byte16对应的ASCII码(国产MCU)";
CM_ SG_ 2418667094 S2P_Cfg13_SW_Ver_Byte9_22 "CSC软件版本号Byte9对应的ASCII码(国产MCU)";
CM_ SG_ 2418667094 S2P_Cfg13_SW_Ver_Byte10_22 "CSC软件版本号Byte10对应的ASCII码(国产MCU)";
CM_ SG_ 2418667094 S2P_Cfg13_SW_Ver_Byte11_22 "CSC软件版本号Byte11对应的ASCII码(国产MCU)";
CM_ SG_ 2418667094 S2P_Cfg13_SW_Ver_Byte12_22 "CSC软件版本号Byte12对应的ASCII码(国产MCU)";
CM_ SG_ 2418667094 S2P_Cfg13_SW_Ver_Byte13_22 "CSC软件版本号Byte13对应的ASCII码(国产MCU)";
CM_ SG_ 2418667094 S2P_Cfg13_SW_Ver_Byte14_22 "CSC软件版本号Byte14对应的ASCII码(国产MCU)";
CM_ SG_ 2418667094 S2P_Cfg13_SW_Ver_Byte15_22 "CSC软件版本号Byte15对应的ASCII码(国产MCU)";
CM_ SG_ 2418667094 S2P_Cfg13_SW_Ver_Byte16_22 "CSC软件版本号最高字节Byte16对应的ASCII码(国产MCU)";
CM_ SG_ 2418667095 S2P_Cfg13_SW_Ver_Byte9_23 "CSC软件版本号Byte9对应的ASCII码(国产MCU)";
CM_ SG_ 2418667095 S2P_Cfg13_SW_Ver_Byte10_23 "CSC软件版本号Byte10对应的ASCII码(国产MCU)";
CM_ SG_ 2418667095 S2P_Cfg13_SW_Ver_Byte11_23 "CSC软件版本号Byte11对应的ASCII码(国产MCU)";
CM_ SG_ 2418667095 S2P_Cfg13_SW_Ver_Byte12_23 "CSC软件版本号Byte12对应的ASCII码(国产MCU)";
CM_ SG_ 2418667095 S2P_Cfg13_SW_Ver_Byte13_23 "CSC软件版本号Byte13对应的ASCII码(国产MCU)";
CM_ SG_ 2418667095 S2P_Cfg13_SW_Ver_Byte14_23 "CSC软件版本号Byte14对应的ASCII码(国产MCU)";
CM_ SG_ 2418667095 S2P_Cfg13_SW_Ver_Byte15_23 "CSC软件版本号Byte15对应的ASCII码(国产MCU)";
CM_ SG_ 2418667095 S2P_Cfg13_SW_Ver_Byte16_23 "CSC软件版本号最高字节Byte16对应的ASCII码(国产MCU)";
CM_ SG_ 2418667096 S2P_Cfg13_SW_Ver_Byte9_24 "CSC软件版本号Byte9对应的ASCII码(国产MCU)";
CM_ SG_ 2418667096 S2P_Cfg13_SW_Ver_Byte10_24 "CSC软件版本号Byte10对应的ASCII码(国产MCU)";
CM_ SG_ 2418667096 S2P_Cfg13_SW_Ver_Byte11_24 "CSC软件版本号Byte11对应的ASCII码(国产MCU)";
CM_ SG_ 2418667096 S2P_Cfg13_SW_Ver_Byte12_24 "CSC软件版本号Byte12对应的ASCII码(国产MCU)";
CM_ SG_ 2418667096 S2P_Cfg13_SW_Ver_Byte13_24 "CSC软件版本号Byte13对应的ASCII码(国产MCU)";
CM_ SG_ 2418667096 S2P_Cfg13_SW_Ver_Byte14_24 "CSC软件版本号Byte14对应的ASCII码(国产MCU)";
CM_ SG_ 2418667096 S2P_Cfg13_SW_Ver_Byte15_24 "CSC软件版本号Byte15对应的ASCII码(国产MCU)";
CM_ SG_ 2418667096 S2P_Cfg13_SW_Ver_Byte16_24 "CSC软件版本号最高字节Byte16对应的ASCII码(国产MCU)";
CM_ SG_ 2418667097 S2P_Cfg13_SW_Ver_Byte9_25 "CSC软件版本号Byte9对应的ASCII码(国产MCU)";
CM_ SG_ 2418667097 S2P_Cfg13_SW_Ver_Byte10_25 "CSC软件版本号Byte10对应的ASCII码(国产MCU)";
CM_ SG_ 2418667097 S2P_Cfg13_SW_Ver_Byte11_25 "CSC软件版本号Byte11对应的ASCII码(国产MCU)";
CM_ SG_ 2418667097 S2P_Cfg13_SW_Ver_Byte12_25 "CSC软件版本号Byte12对应的ASCII码(国产MCU)";
CM_ SG_ 2418667097 S2P_Cfg13_SW_Ver_Byte13_25 "CSC软件版本号Byte13对应的ASCII码(国产MCU)";
CM_ SG_ 2418667097 S2P_Cfg13_SW_Ver_Byte14_25 "CSC软件版本号Byte14对应的ASCII码(国产MCU)";
CM_ SG_ 2418667097 S2P_Cfg13_SW_Ver_Byte15_25 "CSC软件版本号Byte15对应的ASCII码(国产MCU)";
CM_ SG_ 2418667097 S2P_Cfg13_SW_Ver_Byte16_25 "CSC软件版本号最高字节Byte16对应的ASCII码(国产MCU)";
CM_ SG_ 2418667098 S2P_Cfg13_SW_Ver_Byte9_26 "CSC软件版本号Byte9对应的ASCII码(国产MCU)";
CM_ SG_ 2418667098 S2P_Cfg13_SW_Ver_Byte10_26 "CSC软件版本号Byte10对应的ASCII码(国产MCU)";
CM_ SG_ 2418667098 S2P_Cfg13_SW_Ver_Byte11_26 "CSC软件版本号Byte11对应的ASCII码(国产MCU)";
CM_ SG_ 2418667098 S2P_Cfg13_SW_Ver_Byte12_26 "CSC软件版本号Byte12对应的ASCII码(国产MCU)";
CM_ SG_ 2418667098 S2P_Cfg13_SW_Ver_Byte13_26 "CSC软件版本号Byte13对应的ASCII码(国产MCU)";
CM_ SG_ 2418667098 S2P_Cfg13_SW_Ver_Byte14_26 "CSC软件版本号Byte14对应的ASCII码(国产MCU)";
CM_ SG_ 2418667098 S2P_Cfg13_SW_Ver_Byte15_26 "CSC软件版本号Byte15对应的ASCII码(国产MCU)";
CM_ SG_ 2418667098 S2P_Cfg13_SW_Ver_Byte16_26 "CSC软件版本号最高字节Byte16对应的ASCII码(国产MCU)";
CM_ SG_ 2418667099 S2P_Cfg13_SW_Ver_Byte9_27 "CSC软件版本号Byte9对应的ASCII码(国产MCU)";
CM_ SG_ 2418667099 S2P_Cfg13_SW_Ver_Byte10_27 "CSC软件版本号Byte10对应的ASCII码(国产MCU)";
CM_ SG_ 2418667099 S2P_Cfg13_SW_Ver_Byte11_27 "CSC软件版本号Byte11对应的ASCII码(国产MCU)";
CM_ SG_ 2418667099 S2P_Cfg13_SW_Ver_Byte12_27 "CSC软件版本号Byte12对应的ASCII码(国产MCU)";
CM_ SG_ 2418667099 S2P_Cfg13_SW_Ver_Byte13_27 "CSC软件版本号Byte13对应的ASCII码(国产MCU)";
CM_ SG_ 2418667099 S2P_Cfg13_SW_Ver_Byte14_27 "CSC软件版本号Byte14对应的ASCII码(国产MCU)";
CM_ SG_ 2418667099 S2P_Cfg13_SW_Ver_Byte15_27 "CSC软件版本号Byte15对应的ASCII码(国产MCU)";
CM_ SG_ 2418667099 S2P_Cfg13_SW_Ver_Byte16_27 "CSC软件版本号最高字节Byte16对应的ASCII码(国产MCU)";
CM_ SG_ 2418667100 S2P_Cfg13_SW_Ver_Byte9_28 "CSC软件版本号Byte9对应的ASCII码(国产MCU)";
CM_ SG_ 2418667100 S2P_Cfg13_SW_Ver_Byte10_28 "CSC软件版本号Byte10对应的ASCII码(国产MCU)";
CM_ SG_ 2418667100 S2P_Cfg13_SW_Ver_Byte11_28 "CSC软件版本号Byte11对应的ASCII码(国产MCU)";
CM_ SG_ 2418667100 S2P_Cfg13_SW_Ver_Byte12_28 "CSC软件版本号Byte12对应的ASCII码(国产MCU)";
CM_ SG_ 2418667100 S2P_Cfg13_SW_Ver_Byte13_28 "CSC软件版本号Byte13对应的ASCII码(国产MCU)";
CM_ SG_ 2418667100 S2P_Cfg13_SW_Ver_Byte14_28 "CSC软件版本号Byte14对应的ASCII码(国产MCU)";
CM_ SG_ 2418667100 S2P_Cfg13_SW_Ver_Byte15_28 "CSC软件版本号Byte15对应的ASCII码(国产MCU)";
CM_ SG_ 2418667100 S2P_Cfg13_SW_Ver_Byte16_28 "CSC软件版本号最高字节Byte16对应的ASCII码(国产MCU)";
CM_ SG_ 2418667101 S2P_Cfg13_SW_Ver_Byte9_29 "CSC软件版本号Byte9对应的ASCII码(国产MCU)";
CM_ SG_ 2418667101 S2P_Cfg13_SW_Ver_Byte10_29 "CSC软件版本号Byte10对应的ASCII码(国产MCU)";
CM_ SG_ 2418667101 S2P_Cfg13_SW_Ver_Byte11_29 "CSC软件版本号Byte11对应的ASCII码(国产MCU)";
CM_ SG_ 2418667101 S2P_Cfg13_SW_Ver_Byte12_29 "CSC软件版本号Byte12对应的ASCII码(国产MCU)";
CM_ SG_ 2418667101 S2P_Cfg13_SW_Ver_Byte13_29 "CSC软件版本号Byte13对应的ASCII码(国产MCU)";
CM_ SG_ 2418667101 S2P_Cfg13_SW_Ver_Byte14_29 "CSC软件版本号Byte14对应的ASCII码(国产MCU)";
CM_ SG_ 2418667101 S2P_Cfg13_SW_Ver_Byte15_29 "CSC软件版本号Byte15对应的ASCII码(国产MCU)";
CM_ SG_ 2418667101 S2P_Cfg13_SW_Ver_Byte16_29 "CSC软件版本号最高字节Byte16对应的ASCII码(国产MCU)";
CM_ SG_ 2418667102 S2P_Cfg13_SW_Ver_Byte9_30 "CSC软件版本号Byte9对应的ASCII码(国产MCU)";
CM_ SG_ 2418667102 S2P_Cfg13_SW_Ver_Byte10_30 "CSC软件版本号Byte10对应的ASCII码(国产MCU)";
CM_ SG_ 2418667102 S2P_Cfg13_SW_Ver_Byte11_30 "CSC软件版本号Byte11对应的ASCII码(国产MCU)";
CM_ SG_ 2418667102 S2P_Cfg13_SW_Ver_Byte12_30 "CSC软件版本号Byte12对应的ASCII码(国产MCU)";
CM_ SG_ 2418667102 S2P_Cfg13_SW_Ver_Byte13_30 "CSC软件版本号Byte13对应的ASCII码(国产MCU)";
CM_ SG_ 2418667102 S2P_Cfg13_SW_Ver_Byte14_30 "CSC软件版本号Byte14对应的ASCII码(国产MCU)";
CM_ SG_ 2418667102 S2P_Cfg13_SW_Ver_Byte15_30 "CSC软件版本号Byte15对应的ASCII码(国产MCU)";
CM_ SG_ 2418667102 S2P_Cfg13_SW_Ver_Byte16_30 "CSC软件版本号最高字节Byte16对应的ASCII码(国产MCU)";
CM_ SG_ 2418667103 S2P_Cfg13_SW_Ver_Byte9_31 "CSC软件版本号Byte9对应的ASCII码(国产MCU)";
CM_ SG_ 2418667103 S2P_Cfg13_SW_Ver_Byte10_31 "CSC软件版本号Byte10对应的ASCII码(国产MCU)";
CM_ SG_ 2418667103 S2P_Cfg13_SW_Ver_Byte11_31 "CSC软件版本号Byte11对应的ASCII码(国产MCU)";
CM_ SG_ 2418667103 S2P_Cfg13_SW_Ver_Byte12_31 "CSC软件版本号Byte12对应的ASCII码(国产MCU)";
CM_ SG_ 2418667103 S2P_Cfg13_SW_Ver_Byte13_31 "CSC软件版本号Byte13对应的ASCII码(国产MCU)";
CM_ SG_ 2418667103 S2P_Cfg13_SW_Ver_Byte14_31 "CSC软件版本号Byte14对应的ASCII码(国产MCU)";
CM_ SG_ 2418667103 S2P_Cfg13_SW_Ver_Byte15_31 "CSC软件版本号Byte15对应的ASCII码(国产MCU)";
CM_ SG_ 2418667103 S2P_Cfg13_SW_Ver_Byte16_31 "CSC软件版本号最高字节Byte16对应的ASCII码(国产MCU)";
CM_ SG_ 2418667104 S2P_Cfg13_SW_Ver_Byte9_32 "CSC软件版本号Byte9对应的ASCII码(国产MCU)";
CM_ SG_ 2418667104 S2P_Cfg13_SW_Ver_Byte10_32 "CSC软件版本号Byte10对应的ASCII码(国产MCU)";
CM_ SG_ 2418667104 S2P_Cfg13_SW_Ver_Byte11_32 "CSC软件版本号Byte11对应的ASCII码(国产MCU)";
CM_ SG_ 2418667104 S2P_Cfg13_SW_Ver_Byte12_32 "CSC软件版本号Byte12对应的ASCII码(国产MCU)";
CM_ SG_ 2418667104 S2P_Cfg13_SW_Ver_Byte13_32 "CSC软件版本号Byte13对应的ASCII码(国产MCU)";
CM_ SG_ 2418667104 S2P_Cfg13_SW_Ver_Byte14_32 "CSC软件版本号Byte14对应的ASCII码(国产MCU)";
CM_ SG_ 2418667104 S2P_Cfg13_SW_Ver_Byte15_32 "CSC软件版本号Byte15对应的ASCII码(国产MCU)";
CM_ SG_ 2418667104 S2P_Cfg13_SW_Ver_Byte16_32 "CSC软件版本号最高字节Byte16对应的ASCII码(国产MCU)";
CM_ SG_ 2418667105 S2P_Cfg13_SW_Ver_Byte9_33 "CSC软件版本号Byte9对应的ASCII码(国产MCU)";
CM_ SG_ 2418667105 S2P_Cfg13_SW_Ver_Byte10_33 "CSC软件版本号Byte10对应的ASCII码(国产MCU)";
CM_ SG_ 2418667105 S2P_Cfg13_SW_Ver_Byte11_33 "CSC软件版本号Byte11对应的ASCII码(国产MCU)";
CM_ SG_ 2418667105 S2P_Cfg13_SW_Ver_Byte12_33 "CSC软件版本号Byte12对应的ASCII码(国产MCU)";
CM_ SG_ 2418667105 S2P_Cfg13_SW_Ver_Byte13_33 "CSC软件版本号Byte13对应的ASCII码(国产MCU)";
CM_ SG_ 2418667105 S2P_Cfg13_SW_Ver_Byte14_33 "CSC软件版本号Byte14对应的ASCII码(国产MCU)";
CM_ SG_ 2418667105 S2P_Cfg13_SW_Ver_Byte15_33 "CSC软件版本号Byte15对应的ASCII码(国产MCU)";
CM_ SG_ 2418667105 S2P_Cfg13_SW_Ver_Byte16_33 "CSC软件版本号最高字节Byte16对应的ASCII码(国产MCU)";
CM_ SG_ 2418667106 S2P_Cfg13_SW_Ver_Byte9_34 "CSC软件版本号Byte9对应的ASCII码(国产MCU)";
CM_ SG_ 2418667106 S2P_Cfg13_SW_Ver_Byte10_34 "CSC软件版本号Byte10对应的ASCII码(国产MCU)";
CM_ SG_ 2418667106 S2P_Cfg13_SW_Ver_Byte11_34 "CSC软件版本号Byte11对应的ASCII码(国产MCU)";
CM_ SG_ 2418667106 S2P_Cfg13_SW_Ver_Byte12_34 "CSC软件版本号Byte12对应的ASCII码(国产MCU)";
CM_ SG_ 2418667106 S2P_Cfg13_SW_Ver_Byte13_34 "CSC软件版本号Byte13对应的ASCII码(国产MCU)";
CM_ SG_ 2418667106 S2P_Cfg13_SW_Ver_Byte14_34 "CSC软件版本号Byte14对应的ASCII码(国产MCU)";
CM_ SG_ 2418667106 S2P_Cfg13_SW_Ver_Byte15_34 "CSC软件版本号Byte15对应的ASCII码(国产MCU)";
CM_ SG_ 2418667106 S2P_Cfg13_SW_Ver_Byte16_34 "CSC软件版本号最高字节Byte16对应的ASCII码(国产MCU)";
CM_ SG_ 2418667107 S2P_Cfg13_SW_Ver_Byte9_35 "CSC软件版本号Byte9对应的ASCII码(国产MCU)";
CM_ SG_ 2418667107 S2P_Cfg13_SW_Ver_Byte10_35 "CSC软件版本号Byte10对应的ASCII码(国产MCU)";
CM_ SG_ 2418667107 S2P_Cfg13_SW_Ver_Byte11_35 "CSC软件版本号Byte11对应的ASCII码(国产MCU)";
CM_ SG_ 2418667107 S2P_Cfg13_SW_Ver_Byte12_35 "CSC软件版本号Byte12对应的ASCII码(国产MCU)";
CM_ SG_ 2418667107 S2P_Cfg13_SW_Ver_Byte13_35 "CSC软件版本号Byte13对应的ASCII码(国产MCU)";
CM_ SG_ 2418667107 S2P_Cfg13_SW_Ver_Byte14_35 "CSC软件版本号Byte14对应的ASCII码(国产MCU)";
CM_ SG_ 2418667107 S2P_Cfg13_SW_Ver_Byte15_35 "CSC软件版本号Byte15对应的ASCII码(国产MCU)";
CM_ SG_ 2418667107 S2P_Cfg13_SW_Ver_Byte16_35 "CSC软件版本号最高字节Byte16对应的ASCII码(国产MCU)";
CM_ SG_ 2418667108 S2P_Cfg13_SW_Ver_Byte9_36 "CSC软件版本号Byte9对应的ASCII码(国产MCU)";
CM_ SG_ 2418667108 S2P_Cfg13_SW_Ver_Byte10_36 "CSC软件版本号Byte10对应的ASCII码(国产MCU)";
CM_ SG_ 2418667108 S2P_Cfg13_SW_Ver_Byte11_36 "CSC软件版本号Byte11对应的ASCII码(国产MCU)";
CM_ SG_ 2418667108 S2P_Cfg13_SW_Ver_Byte12_36 "CSC软件版本号Byte12对应的ASCII码(国产MCU)";
CM_ SG_ 2418667108 S2P_Cfg13_SW_Ver_Byte13_36 "CSC软件版本号Byte13对应的ASCII码(国产MCU)";
CM_ SG_ 2418667108 S2P_Cfg13_SW_Ver_Byte14_36 "CSC软件版本号Byte14对应的ASCII码(国产MCU)";
CM_ SG_ 2418667108 S2P_Cfg13_SW_Ver_Byte15_36 "CSC软件版本号Byte15对应的ASCII码(国产MCU)";
CM_ SG_ 2418667108 S2P_Cfg13_SW_Ver_Byte16_36 "CSC软件版本号最高字节Byte16对应的ASCII码(国产MCU)";
CM_ SG_ 2418667109 S2P_Cfg13_SW_Ver_Byte9_37 "CSC软件版本号Byte9对应的ASCII码(国产MCU)";
CM_ SG_ 2418667109 S2P_Cfg13_SW_Ver_Byte10_37 "CSC软件版本号Byte10对应的ASCII码(国产MCU)";
CM_ SG_ 2418667109 S2P_Cfg13_SW_Ver_Byte11_37 "CSC软件版本号Byte11对应的ASCII码(国产MCU)";
CM_ SG_ 2418667109 S2P_Cfg13_SW_Ver_Byte12_37 "CSC软件版本号Byte12对应的ASCII码(国产MCU)";
CM_ SG_ 2418667109 S2P_Cfg13_SW_Ver_Byte13_37 "CSC软件版本号Byte13对应的ASCII码(国产MCU)";
CM_ SG_ 2418667109 S2P_Cfg13_SW_Ver_Byte14_37 "CSC软件版本号Byte14对应的ASCII码(国产MCU)";
CM_ SG_ 2418667109 S2P_Cfg13_SW_Ver_Byte15_37 "CSC软件版本号Byte15对应的ASCII码(国产MCU)";
CM_ SG_ 2418667109 S2P_Cfg13_SW_Ver_Byte16_37 "CSC软件版本号最高字节Byte16对应的ASCII码(国产MCU)";
CM_ SG_ 2418667110 S2P_Cfg13_SW_Ver_Byte9_38 "CSC软件版本号Byte9对应的ASCII码(国产MCU)";
CM_ SG_ 2418667110 S2P_Cfg13_SW_Ver_Byte10_38 "CSC软件版本号Byte10对应的ASCII码(国产MCU)";
CM_ SG_ 2418667110 S2P_Cfg13_SW_Ver_Byte11_38 "CSC软件版本号Byte11对应的ASCII码(国产MCU)";
CM_ SG_ 2418667110 S2P_Cfg13_SW_Ver_Byte12_38 "CSC软件版本号Byte12对应的ASCII码(国产MCU)";
CM_ SG_ 2418667110 S2P_Cfg13_SW_Ver_Byte13_38 "CSC软件版本号Byte13对应的ASCII码(国产MCU)";
CM_ SG_ 2418667110 S2P_Cfg13_SW_Ver_Byte14_38 "CSC软件版本号Byte14对应的ASCII码(国产MCU)";
CM_ SG_ 2418667110 S2P_Cfg13_SW_Ver_Byte15_38 "CSC软件版本号Byte15对应的ASCII码(国产MCU)";
CM_ SG_ 2418667110 S2P_Cfg13_SW_Ver_Byte16_38 "CSC软件版本号最高字节Byte16对应的ASCII码(国产MCU)";
CM_ SG_ 2418667111 S2P_Cfg13_SW_Ver_Byte9_39 "CSC软件版本号Byte9对应的ASCII码(国产MCU)";
CM_ SG_ 2418667111 S2P_Cfg13_SW_Ver_Byte10_39 "CSC软件版本号Byte10对应的ASCII码(国产MCU)";
CM_ SG_ 2418667111 S2P_Cfg13_SW_Ver_Byte11_39 "CSC软件版本号Byte11对应的ASCII码(国产MCU)";
CM_ SG_ 2418667111 S2P_Cfg13_SW_Ver_Byte12_39 "CSC软件版本号Byte12对应的ASCII码(国产MCU)";
CM_ SG_ 2418667111 S2P_Cfg13_SW_Ver_Byte13_39 "CSC软件版本号Byte13对应的ASCII码(国产MCU)";
CM_ SG_ 2418667111 S2P_Cfg13_SW_Ver_Byte14_39 "CSC软件版本号Byte14对应的ASCII码(国产MCU)";
CM_ SG_ 2418667111 S2P_Cfg13_SW_Ver_Byte15_39 "CSC软件版本号Byte15对应的ASCII码(国产MCU)";
CM_ SG_ 2418667111 S2P_Cfg13_SW_Ver_Byte16_39 "CSC软件版本号最高字节Byte16对应的ASCII码(国产MCU)";
CM_ SG_ 2418667112 S2P_Cfg13_SW_Ver_Byte9_40 "CSC软件版本号Byte9对应的ASCII码(国产MCU)";
CM_ SG_ 2418667112 S2P_Cfg13_SW_Ver_Byte10_40 "CSC软件版本号Byte10对应的ASCII码(国产MCU)";
CM_ SG_ 2418667112 S2P_Cfg13_SW_Ver_Byte11_40 "CSC软件版本号Byte11对应的ASCII码(国产MCU)";
CM_ SG_ 2418667112 S2P_Cfg13_SW_Ver_Byte12_40 "CSC软件版本号Byte12对应的ASCII码(国产MCU)";
CM_ SG_ 2418667112 S2P_Cfg13_SW_Ver_Byte13_40 "CSC软件版本号Byte13对应的ASCII码(国产MCU)";
CM_ SG_ 2418667112 S2P_Cfg13_SW_Ver_Byte14_40 "CSC软件版本号Byte14对应的ASCII码(国产MCU)";
CM_ SG_ 2418667112 S2P_Cfg13_SW_Ver_Byte15_40 "CSC软件版本号Byte15对应的ASCII码(国产MCU)";
CM_ SG_ 2418667112 S2P_Cfg13_SW_Ver_Byte16_40 "CSC软件版本号最高字节Byte16对应的ASCII码(国产MCU)";
CM_ SG_ 2418667113 S2P_Cfg13_SW_Ver_Byte9_41 "CSC软件版本号Byte9对应的ASCII码(国产MCU)";
CM_ SG_ 2418667113 S2P_Cfg13_SW_Ver_Byte10_41 "CSC软件版本号Byte10对应的ASCII码(国产MCU)";
CM_ SG_ 2418667113 S2P_Cfg13_SW_Ver_Byte11_41 "CSC软件版本号Byte11对应的ASCII码(国产MCU)";
CM_ SG_ 2418667113 S2P_Cfg13_SW_Ver_Byte12_41 "CSC软件版本号Byte12对应的ASCII码(国产MCU)";
CM_ SG_ 2418667113 S2P_Cfg13_SW_Ver_Byte13_41 "CSC软件版本号Byte13对应的ASCII码(国产MCU)";
CM_ SG_ 2418667113 S2P_Cfg13_SW_Ver_Byte14_41 "CSC软件版本号Byte14对应的ASCII码(国产MCU)";
CM_ SG_ 2418667113 S2P_Cfg13_SW_Ver_Byte15_41 "CSC软件版本号Byte15对应的ASCII码(国产MCU)";
CM_ SG_ 2418667113 S2P_Cfg13_SW_Ver_Byte16_41 "CSC软件版本号最高字节Byte16对应的ASCII码(国产MCU)";
CM_ SG_ 2418667114 S2P_Cfg13_SW_Ver_Byte9_42 "CSC软件版本号Byte9对应的ASCII码(国产MCU)";
CM_ SG_ 2418667114 S2P_Cfg13_SW_Ver_Byte10_42 "CSC软件版本号Byte10对应的ASCII码(国产MCU)";
CM_ SG_ 2418667114 S2P_Cfg13_SW_Ver_Byte11_42 "CSC软件版本号Byte11对应的ASCII码(国产MCU)";
CM_ SG_ 2418667114 S2P_Cfg13_SW_Ver_Byte12_42 "CSC软件版本号Byte12对应的ASCII码(国产MCU)";
CM_ SG_ 2418667114 S2P_Cfg13_SW_Ver_Byte13_42 "CSC软件版本号Byte13对应的ASCII码(国产MCU)";
CM_ SG_ 2418667114 S2P_Cfg13_SW_Ver_Byte14_42 "CSC软件版本号Byte14对应的ASCII码(国产MCU)";
CM_ SG_ 2418667114 S2P_Cfg13_SW_Ver_Byte15_42 "CSC软件版本号Byte15对应的ASCII码(国产MCU)";
CM_ SG_ 2418667114 S2P_Cfg13_SW_Ver_Byte16_42 "CSC软件版本号最高字节Byte16对应的ASCII码(国产MCU)";
CM_ SG_ 2418667115 S2P_Cfg13_SW_Ver_Byte9_43 "CSC软件版本号Byte9对应的ASCII码(国产MCU)";
CM_ SG_ 2418667115 S2P_Cfg13_SW_Ver_Byte10_43 "CSC软件版本号Byte10对应的ASCII码(国产MCU)";
CM_ SG_ 2418667115 S2P_Cfg13_SW_Ver_Byte11_43 "CSC软件版本号Byte11对应的ASCII码(国产MCU)";
CM_ SG_ 2418667115 S2P_Cfg13_SW_Ver_Byte12_43 "CSC软件版本号Byte12对应的ASCII码(国产MCU)";
CM_ SG_ 2418667115 S2P_Cfg13_SW_Ver_Byte13_43 "CSC软件版本号Byte13对应的ASCII码(国产MCU)";
CM_ SG_ 2418667115 S2P_Cfg13_SW_Ver_Byte14_43 "CSC软件版本号Byte14对应的ASCII码(国产MCU)";
CM_ SG_ 2418667115 S2P_Cfg13_SW_Ver_Byte15_43 "CSC软件版本号Byte15对应的ASCII码(国产MCU)";
CM_ SG_ 2418667115 S2P_Cfg13_SW_Ver_Byte16_43 "CSC软件版本号最高字节Byte16对应的ASCII码(国产MCU)";
CM_ SG_ 2418667116 S2P_Cfg13_SW_Ver_Byte9_44 "CSC软件版本号Byte9对应的ASCII码(国产MCU)";
CM_ SG_ 2418667116 S2P_Cfg13_SW_Ver_Byte10_44 "CSC软件版本号Byte10对应的ASCII码(国产MCU)";
CM_ SG_ 2418667116 S2P_Cfg13_SW_Ver_Byte11_44 "CSC软件版本号Byte11对应的ASCII码(国产MCU)";
CM_ SG_ 2418667116 S2P_Cfg13_SW_Ver_Byte12_44 "CSC软件版本号Byte12对应的ASCII码(国产MCU)";
CM_ SG_ 2418667116 S2P_Cfg13_SW_Ver_Byte13_44 "CSC软件版本号Byte13对应的ASCII码(国产MCU)";
CM_ SG_ 2418667116 S2P_Cfg13_SW_Ver_Byte14_44 "CSC软件版本号Byte14对应的ASCII码(国产MCU)";
CM_ SG_ 2418667116 S2P_Cfg13_SW_Ver_Byte15_44 "CSC软件版本号Byte15对应的ASCII码(国产MCU)";
CM_ SG_ 2418667116 S2P_Cfg13_SW_Ver_Byte16_44 "CSC软件版本号最高字节Byte16对应的ASCII码(国产MCU)";
CM_ SG_ 2418667117 S2P_Cfg13_SW_Ver_Byte9_45 "CSC软件版本号Byte9对应的ASCII码(国产MCU)";
CM_ SG_ 2418667117 S2P_Cfg13_SW_Ver_Byte10_45 "CSC软件版本号Byte10对应的ASCII码(国产MCU)";
CM_ SG_ 2418667117 S2P_Cfg13_SW_Ver_Byte11_45 "CSC软件版本号Byte11对应的ASCII码(国产MCU)";
CM_ SG_ 2418667117 S2P_Cfg13_SW_Ver_Byte12_45 "CSC软件版本号Byte12对应的ASCII码(国产MCU)";
CM_ SG_ 2418667117 S2P_Cfg13_SW_Ver_Byte13_45 "CSC软件版本号Byte13对应的ASCII码(国产MCU)";
CM_ SG_ 2418667117 S2P_Cfg13_SW_Ver_Byte14_45 "CSC软件版本号Byte14对应的ASCII码(国产MCU)";
CM_ SG_ 2418667117 S2P_Cfg13_SW_Ver_Byte15_45 "CSC软件版本号Byte15对应的ASCII码(国产MCU)";
CM_ SG_ 2418667117 S2P_Cfg13_SW_Ver_Byte16_45 "CSC软件版本号最高字节Byte16对应的ASCII码(国产MCU)";
CM_ SG_ 2418667118 S2P_Cfg13_SW_Ver_Byte9_46 "CSC软件版本号Byte9对应的ASCII码(国产MCU)";
CM_ SG_ 2418667118 S2P_Cfg13_SW_Ver_Byte10_46 "CSC软件版本号Byte10对应的ASCII码(国产MCU)";
CM_ SG_ 2418667118 S2P_Cfg13_SW_Ver_Byte11_46 "CSC软件版本号Byte11对应的ASCII码(国产MCU)";
CM_ SG_ 2418667118 S2P_Cfg13_SW_Ver_Byte12_46 "CSC软件版本号Byte12对应的ASCII码(国产MCU)";
CM_ SG_ 2418667118 S2P_Cfg13_SW_Ver_Byte13_46 "CSC软件版本号Byte13对应的ASCII码(国产MCU)";
CM_ SG_ 2418667118 S2P_Cfg13_SW_Ver_Byte14_46 "CSC软件版本号Byte14对应的ASCII码(国产MCU)";
CM_ SG_ 2418667118 S2P_Cfg13_SW_Ver_Byte15_46 "CSC软件版本号Byte15对应的ASCII码(国产MCU)";
CM_ SG_ 2418667118 S2P_Cfg13_SW_Ver_Byte16_46 "CSC软件版本号最高字节Byte16对应的ASCII码(国产MCU)";
CM_ SG_ 2418667119 S2P_Cfg13_SW_Ver_Byte9_47 "CSC软件版本号Byte9对应的ASCII码(国产MCU)";
CM_ SG_ 2418667119 S2P_Cfg13_SW_Ver_Byte10_47 "CSC软件版本号Byte10对应的ASCII码(国产MCU)";
CM_ SG_ 2418667119 S2P_Cfg13_SW_Ver_Byte11_47 "CSC软件版本号Byte11对应的ASCII码(国产MCU)";
CM_ SG_ 2418667119 S2P_Cfg13_SW_Ver_Byte12_47 "CSC软件版本号Byte12对应的ASCII码(国产MCU)";
CM_ SG_ 2418667119 S2P_Cfg13_SW_Ver_Byte13_47 "CSC软件版本号Byte13对应的ASCII码(国产MCU)";
CM_ SG_ 2418667119 S2P_Cfg13_SW_Ver_Byte14_47 "CSC软件版本号Byte14对应的ASCII码(国产MCU)";
CM_ SG_ 2418667119 S2P_Cfg13_SW_Ver_Byte15_47 "CSC软件版本号Byte15对应的ASCII码(国产MCU)";
CM_ SG_ 2418667119 S2P_Cfg13_SW_Ver_Byte16_47 "CSC软件版本号最高字节Byte16对应的ASCII码(国产MCU)";
CM_ SG_ 2418667120 S2P_Cfg13_SW_Ver_Byte9_48 "CSC软件版本号Byte9对应的ASCII码(国产MCU)";
CM_ SG_ 2418667120 S2P_Cfg13_SW_Ver_Byte10_48 "CSC软件版本号Byte10对应的ASCII码(国产MCU)";
CM_ SG_ 2418667120 S2P_Cfg13_SW_Ver_Byte11_48 "CSC软件版本号Byte11对应的ASCII码(国产MCU)";
CM_ SG_ 2418667120 S2P_Cfg13_SW_Ver_Byte12_48 "CSC软件版本号Byte12对应的ASCII码(国产MCU)";
CM_ SG_ 2418667120 S2P_Cfg13_SW_Ver_Byte13_48 "CSC软件版本号Byte13对应的ASCII码(国产MCU)";
CM_ SG_ 2418667120 S2P_Cfg13_SW_Ver_Byte14_48 "CSC软件版本号Byte14对应的ASCII码(国产MCU)";
CM_ SG_ 2418667120 S2P_Cfg13_SW_Ver_Byte15_48 "CSC软件版本号Byte15对应的ASCII码(国产MCU)";
CM_ SG_ 2418667120 S2P_Cfg13_SW_Ver_Byte16_48 "CSC软件版本号最高字节Byte16对应的ASCII码(国产MCU)";
CM_ SG_ 2418667121 S2P_Cfg13_SW_Ver_Byte9_49 "CSC软件版本号Byte9对应的ASCII码(国产MCU)";
CM_ SG_ 2418667121 S2P_Cfg13_SW_Ver_Byte10_49 "CSC软件版本号Byte10对应的ASCII码(国产MCU)";
CM_ SG_ 2418667121 S2P_Cfg13_SW_Ver_Byte11_49 "CSC软件版本号Byte11对应的ASCII码(国产MCU)";
CM_ SG_ 2418667121 S2P_Cfg13_SW_Ver_Byte12_49 "CSC软件版本号Byte12对应的ASCII码(国产MCU)";
CM_ SG_ 2418667121 S2P_Cfg13_SW_Ver_Byte13_49 "CSC软件版本号Byte13对应的ASCII码(国产MCU)";
CM_ SG_ 2418667121 S2P_Cfg13_SW_Ver_Byte14_49 "CSC软件版本号Byte14对应的ASCII码(国产MCU)";
CM_ SG_ 2418667121 S2P_Cfg13_SW_Ver_Byte15_49 "CSC软件版本号Byte15对应的ASCII码(国产MCU)";
CM_ SG_ 2418667121 S2P_Cfg13_SW_Ver_Byte16_49 "CSC软件版本号最高字节Byte16对应的ASCII码(国产MCU)";
CM_ SG_ 2418667122 S2P_Cfg13_SW_Ver_Byte9_50 "CSC软件版本号Byte9对应的ASCII码(国产MCU)";
CM_ SG_ 2418667122 S2P_Cfg13_SW_Ver_Byte10_50 "CSC软件版本号Byte10对应的ASCII码(国产MCU)";
CM_ SG_ 2418667122 S2P_Cfg13_SW_Ver_Byte11_50 "CSC软件版本号Byte11对应的ASCII码(国产MCU)";
CM_ SG_ 2418667122 S2P_Cfg13_SW_Ver_Byte12_50 "CSC软件版本号Byte12对应的ASCII码(国产MCU)";
CM_ SG_ 2418667122 S2P_Cfg13_SW_Ver_Byte13_50 "CSC软件版本号Byte13对应的ASCII码(国产MCU)";
CM_ SG_ 2418667122 S2P_Cfg13_SW_Ver_Byte14_50 "CSC软件版本号Byte14对应的ASCII码(国产MCU)";
CM_ SG_ 2418667122 S2P_Cfg13_SW_Ver_Byte15_50 "CSC软件版本号Byte15对应的ASCII码(国产MCU)";
CM_ SG_ 2418667122 S2P_Cfg13_SW_Ver_Byte16_50 "CSC软件版本号最高字节Byte16对应的ASCII码(国产MCU)";
CM_ SG_ 2418667123 S2P_Cfg13_SW_Ver_Byte9_51 "CSC软件版本号Byte9对应的ASCII码(国产MCU)";
CM_ SG_ 2418667123 S2P_Cfg13_SW_Ver_Byte10_51 "CSC软件版本号Byte10对应的ASCII码(国产MCU)";
CM_ SG_ 2418667123 S2P_Cfg13_SW_Ver_Byte11_51 "CSC软件版本号Byte11对应的ASCII码(国产MCU)";
CM_ SG_ 2418667123 S2P_Cfg13_SW_Ver_Byte12_51 "CSC软件版本号Byte12对应的ASCII码(国产MCU)";
CM_ SG_ 2418667123 S2P_Cfg13_SW_Ver_Byte13_51 "CSC软件版本号Byte13对应的ASCII码(国产MCU)";
CM_ SG_ 2418667123 S2P_Cfg13_SW_Ver_Byte14_51 "CSC软件版本号Byte14对应的ASCII码(国产MCU)";
CM_ SG_ 2418667123 S2P_Cfg13_SW_Ver_Byte15_51 "CSC软件版本号Byte15对应的ASCII码(国产MCU)";
CM_ SG_ 2418667123 S2P_Cfg13_SW_Ver_Byte16_51 "CSC软件版本号最高字节Byte16对应的ASCII码(国产MCU)";
CM_ SG_ 2418667124 S2P_Cfg13_SW_Ver_Byte9_52 "CSC软件版本号Byte9对应的ASCII码(国产MCU)";
CM_ SG_ 2418667124 S2P_Cfg13_SW_Ver_Byte10_52 "CSC软件版本号Byte10对应的ASCII码(国产MCU)";
CM_ SG_ 2418667124 S2P_Cfg13_SW_Ver_Byte11_52 "CSC软件版本号Byte11对应的ASCII码(国产MCU)";
CM_ SG_ 2418667124 S2P_Cfg13_SW_Ver_Byte12_52 "CSC软件版本号Byte12对应的ASCII码(国产MCU)";
CM_ SG_ 2418667124 S2P_Cfg13_SW_Ver_Byte13_52 "CSC软件版本号Byte13对应的ASCII码(国产MCU)";
CM_ SG_ 2418667124 S2P_Cfg13_SW_Ver_Byte14_52 "CSC软件版本号Byte14对应的ASCII码(国产MCU)";
CM_ SG_ 2418667124 S2P_Cfg13_SW_Ver_Byte15_52 "CSC软件版本号Byte15对应的ASCII码(国产MCU)";
CM_ SG_ 2418667124 S2P_Cfg13_SW_Ver_Byte16_52 "CSC软件版本号最高字节Byte16对应的ASCII码(国产MCU)";
CM_ SG_ 2418667125 S2P_Cfg13_SW_Ver_Byte9_53 "CSC软件版本号Byte9对应的ASCII码(国产MCU)";
CM_ SG_ 2418667125 S2P_Cfg13_SW_Ver_Byte10_53 "CSC软件版本号Byte10对应的ASCII码(国产MCU)";
CM_ SG_ 2418667125 S2P_Cfg13_SW_Ver_Byte11_53 "CSC软件版本号Byte11对应的ASCII码(国产MCU)";
CM_ SG_ 2418667125 S2P_Cfg13_SW_Ver_Byte12_53 "CSC软件版本号Byte12对应的ASCII码(国产MCU)";
CM_ SG_ 2418667125 S2P_Cfg13_SW_Ver_Byte13_53 "CSC软件版本号Byte13对应的ASCII码(国产MCU)";
CM_ SG_ 2418667125 S2P_Cfg13_SW_Ver_Byte14_53 "CSC软件版本号Byte14对应的ASCII码(国产MCU)";
CM_ SG_ 2418667125 S2P_Cfg13_SW_Ver_Byte15_53 "CSC软件版本号Byte15对应的ASCII码(国产MCU)";
CM_ SG_ 2418667125 S2P_Cfg13_SW_Ver_Byte16_53 "CSC软件版本号最高字节Byte16对应的ASCII码(国产MCU)";
CM_ SG_ 2418667126 S2P_Cfg13_SW_Ver_Byte9_54 "CSC软件版本号Byte9对应的ASCII码(国产MCU)";
CM_ SG_ 2418667126 S2P_Cfg13_SW_Ver_Byte10_54 "CSC软件版本号Byte10对应的ASCII码(国产MCU)";
CM_ SG_ 2418667126 S2P_Cfg13_SW_Ver_Byte11_54 "CSC软件版本号Byte11对应的ASCII码(国产MCU)";
CM_ SG_ 2418667126 S2P_Cfg13_SW_Ver_Byte12_54 "CSC软件版本号Byte12对应的ASCII码(国产MCU)";
CM_ SG_ 2418667126 S2P_Cfg13_SW_Ver_Byte13_54 "CSC软件版本号Byte13对应的ASCII码(国产MCU)";
CM_ SG_ 2418667126 S2P_Cfg13_SW_Ver_Byte14_54 "CSC软件版本号Byte14对应的ASCII码(国产MCU)";
CM_ SG_ 2418667126 S2P_Cfg13_SW_Ver_Byte15_54 "CSC软件版本号Byte15对应的ASCII码(国产MCU)";
CM_ SG_ 2418667126 S2P_Cfg13_SW_Ver_Byte16_54 "CSC软件版本号最高字节Byte16对应的ASCII码(国产MCU)";
CM_ SG_ 2418667127 S2P_Cfg13_SW_Ver_Byte9_55 "CSC软件版本号Byte9对应的ASCII码(国产MCU)";
CM_ SG_ 2418667127 S2P_Cfg13_SW_Ver_Byte10_55 "CSC软件版本号Byte10对应的ASCII码(国产MCU)";
CM_ SG_ 2418667127 S2P_Cfg13_SW_Ver_Byte11_55 "CSC软件版本号Byte11对应的ASCII码(国产MCU)";
CM_ SG_ 2418667127 S2P_Cfg13_SW_Ver_Byte12_55 "CSC软件版本号Byte12对应的ASCII码(国产MCU)";
CM_ SG_ 2418667127 S2P_Cfg13_SW_Ver_Byte13_55 "CSC软件版本号Byte13对应的ASCII码(国产MCU)";
CM_ SG_ 2418667127 S2P_Cfg13_SW_Ver_Byte14_55 "CSC软件版本号Byte14对应的ASCII码(国产MCU)";
CM_ SG_ 2418667127 S2P_Cfg13_SW_Ver_Byte15_55 "CSC软件版本号Byte15对应的ASCII码(国产MCU)";
CM_ SG_ 2418667127 S2P_Cfg13_SW_Ver_Byte16_55 "CSC软件版本号最高字节Byte16对应的ASCII码(国产MCU)";
CM_ SG_ 2418667128 S2P_Cfg13_SW_Ver_Byte9_56 "CSC软件版本号Byte9对应的ASCII码(国产MCU)";
CM_ SG_ 2418667128 S2P_Cfg13_SW_Ver_Byte10_56 "CSC软件版本号Byte10对应的ASCII码(国产MCU)";
CM_ SG_ 2418667128 S2P_Cfg13_SW_Ver_Byte11_56 "CSC软件版本号Byte11对应的ASCII码(国产MCU)";
CM_ SG_ 2418667128 S2P_Cfg13_SW_Ver_Byte12_56 "CSC软件版本号Byte12对应的ASCII码(国产MCU)";
CM_ SG_ 2418667128 S2P_Cfg13_SW_Ver_Byte13_56 "CSC软件版本号Byte13对应的ASCII码(国产MCU)";
CM_ SG_ 2418667128 S2P_Cfg13_SW_Ver_Byte14_56 "CSC软件版本号Byte14对应的ASCII码(国产MCU)";
CM_ SG_ 2418667128 S2P_Cfg13_SW_Ver_Byte15_56 "CSC软件版本号Byte15对应的ASCII码(国产MCU)";
CM_ SG_ 2418667128 S2P_Cfg13_SW_Ver_Byte16_56 "CSC软件版本号最高字节Byte16对应的ASCII码(国产MCU)";
CM_ SG_ 2418667129 S2P_Cfg13_SW_Ver_Byte9_57 "CSC软件版本号Byte9对应的ASCII码(国产MCU)";
CM_ SG_ 2418667129 S2P_Cfg13_SW_Ver_Byte10_57 "CSC软件版本号Byte10对应的ASCII码(国产MCU)";
CM_ SG_ 2418667129 S2P_Cfg13_SW_Ver_Byte11_57 "CSC软件版本号Byte11对应的ASCII码(国产MCU)";
CM_ SG_ 2418667129 S2P_Cfg13_SW_Ver_Byte12_57 "CSC软件版本号Byte12对应的ASCII码(国产MCU)";
CM_ SG_ 2418667129 S2P_Cfg13_SW_Ver_Byte13_57 "CSC软件版本号Byte13对应的ASCII码(国产MCU)";
CM_ SG_ 2418667129 S2P_Cfg13_SW_Ver_Byte14_57 "CSC软件版本号Byte14对应的ASCII码(国产MCU)";
CM_ SG_ 2418667129 S2P_Cfg13_SW_Ver_Byte15_57 "CSC软件版本号Byte15对应的ASCII码(国产MCU)";
CM_ SG_ 2418667129 S2P_Cfg13_SW_Ver_Byte16_57 "CSC软件版本号最高字节Byte16对应的ASCII码(国产MCU)";
CM_ SG_ 2418667130 S2P_Cfg13_SW_Ver_Byte9_58 "CSC软件版本号Byte9对应的ASCII码(国产MCU)";
CM_ SG_ 2418667130 S2P_Cfg13_SW_Ver_Byte10_58 "CSC软件版本号Byte10对应的ASCII码(国产MCU)";
CM_ SG_ 2418667130 S2P_Cfg13_SW_Ver_Byte11_58 "CSC软件版本号Byte11对应的ASCII码(国产MCU)";
CM_ SG_ 2418667130 S2P_Cfg13_SW_Ver_Byte12_58 "CSC软件版本号Byte12对应的ASCII码(国产MCU)";
CM_ SG_ 2418667130 S2P_Cfg13_SW_Ver_Byte13_58 "CSC软件版本号Byte13对应的ASCII码(国产MCU)";
CM_ SG_ 2418667130 S2P_Cfg13_SW_Ver_Byte14_58 "CSC软件版本号Byte14对应的ASCII码(国产MCU)";
CM_ SG_ 2418667130 S2P_Cfg13_SW_Ver_Byte15_58 "CSC软件版本号Byte15对应的ASCII码(国产MCU)";
CM_ SG_ 2418667130 S2P_Cfg13_SW_Ver_Byte16_58 "CSC软件版本号最高字节Byte16对应的ASCII码(国产MCU)";
CM_ SG_ 2418667131 S2P_Cfg13_SW_Ver_Byte9_59 "CSC软件版本号Byte9对应的ASCII码(国产MCU)";
CM_ SG_ 2418667131 S2P_Cfg13_SW_Ver_Byte10_59 "CSC软件版本号Byte10对应的ASCII码(国产MCU)";
CM_ SG_ 2418667131 S2P_Cfg13_SW_Ver_Byte11_59 "CSC软件版本号Byte11对应的ASCII码(国产MCU)";
CM_ SG_ 2418667131 S2P_Cfg13_SW_Ver_Byte12_59 "CSC软件版本号Byte12对应的ASCII码(国产MCU)";
CM_ SG_ 2418667131 S2P_Cfg13_SW_Ver_Byte13_59 "CSC软件版本号Byte13对应的ASCII码(国产MCU)";
CM_ SG_ 2418667131 S2P_Cfg13_SW_Ver_Byte14_59 "CSC软件版本号Byte14对应的ASCII码(国产MCU)";
CM_ SG_ 2418667131 S2P_Cfg13_SW_Ver_Byte15_59 "CSC软件版本号Byte15对应的ASCII码(国产MCU)";
CM_ SG_ 2418667131 S2P_Cfg13_SW_Ver_Byte16_59 "CSC软件版本号最高字节Byte16对应的ASCII码(国产MCU)";
CM_ SG_ 2418667132 S2P_Cfg13_SW_Ver_Byte9_60 "CSC软件版本号Byte9对应的ASCII码(国产MCU)";
CM_ SG_ 2418667132 S2P_Cfg13_SW_Ver_Byte10_60 "CSC软件版本号Byte10对应的ASCII码(国产MCU)";
CM_ SG_ 2418667132 S2P_Cfg13_SW_Ver_Byte11_60 "CSC软件版本号Byte11对应的ASCII码(国产MCU)";
CM_ SG_ 2418667132 S2P_Cfg13_SW_Ver_Byte12_60 "CSC软件版本号Byte12对应的ASCII码(国产MCU)";
CM_ SG_ 2418667132 S2P_Cfg13_SW_Ver_Byte13_60 "CSC软件版本号Byte13对应的ASCII码(国产MCU)";
CM_ SG_ 2418667132 S2P_Cfg13_SW_Ver_Byte14_60 "CSC软件版本号Byte14对应的ASCII码(国产MCU)";
CM_ SG_ 2418667132 S2P_Cfg13_SW_Ver_Byte15_60 "CSC软件版本号Byte15对应的ASCII码(国产MCU)";
CM_ SG_ 2418667132 S2P_Cfg13_SW_Ver_Byte16_60 "CSC软件版本号最高字节Byte16对应的ASCII码(国产MCU)";
CM_ SG_ 2418667133 S2P_Cfg13_SW_Ver_Byte9_61 "CSC软件版本号Byte9对应的ASCII码(国产MCU)";
CM_ SG_ 2418667133 S2P_Cfg13_SW_Ver_Byte10_61 "CSC软件版本号Byte10对应的ASCII码(国产MCU)";
CM_ SG_ 2418667133 S2P_Cfg13_SW_Ver_Byte11_61 "CSC软件版本号Byte11对应的ASCII码(国产MCU)";
CM_ SG_ 2418667133 S2P_Cfg13_SW_Ver_Byte12_61 "CSC软件版本号Byte12对应的ASCII码(国产MCU)";
CM_ SG_ 2418667133 S2P_Cfg13_SW_Ver_Byte13_61 "CSC软件版本号Byte13对应的ASCII码(国产MCU)";
CM_ SG_ 2418667133 S2P_Cfg13_SW_Ver_Byte14_61 "CSC软件版本号Byte14对应的ASCII码(国产MCU)";
CM_ SG_ 2418667133 S2P_Cfg13_SW_Ver_Byte15_61 "CSC软件版本号Byte15对应的ASCII码(国产MCU)";
CM_ SG_ 2418667133 S2P_Cfg13_SW_Ver_Byte16_61 "CSC软件版本号最高字节Byte16对应的ASCII码(国产MCU)";
CM_ SG_ 2418667134 S2P_Cfg13_SW_Ver_Byte9_62 "CSC软件版本号Byte9对应的ASCII码(国产MCU)";
CM_ SG_ 2418667134 S2P_Cfg13_SW_Ver_Byte10_62 "CSC软件版本号Byte10对应的ASCII码(国产MCU)";
CM_ SG_ 2418667134 S2P_Cfg13_SW_Ver_Byte11_62 "CSC软件版本号Byte11对应的ASCII码(国产MCU)";
CM_ SG_ 2418667134 S2P_Cfg13_SW_Ver_Byte12_62 "CSC软件版本号Byte12对应的ASCII码(国产MCU)";
CM_ SG_ 2418667134 S2P_Cfg13_SW_Ver_Byte13_62 "CSC软件版本号Byte13对应的ASCII码(国产MCU)";
CM_ SG_ 2418667134 S2P_Cfg13_SW_Ver_Byte14_62 "CSC软件版本号Byte14对应的ASCII码(国产MCU)";
CM_ SG_ 2418667134 S2P_Cfg13_SW_Ver_Byte15_62 "CSC软件版本号Byte15对应的ASCII码(国产MCU)";
CM_ SG_ 2418667134 S2P_Cfg13_SW_Ver_Byte16_62 "CSC软件版本号最高字节Byte16对应的ASCII码(国产MCU)";
CM_ SG_ 2418667135 S2P_Cfg13_SW_Ver_Byte9_63 "CSC软件版本号Byte9对应的ASCII码(国产MCU)";
CM_ SG_ 2418667135 S2P_Cfg13_SW_Ver_Byte10_63 "CSC软件版本号Byte10对应的ASCII码(国产MCU)";
CM_ SG_ 2418667135 S2P_Cfg13_SW_Ver_Byte11_63 "CSC软件版本号Byte11对应的ASCII码(国产MCU)";
CM_ SG_ 2418667135 S2P_Cfg13_SW_Ver_Byte12_63 "CSC软件版本号Byte12对应的ASCII码(国产MCU)";
CM_ SG_ 2418667135 S2P_Cfg13_SW_Ver_Byte13_63 "CSC软件版本号Byte13对应的ASCII码(国产MCU)";
CM_ SG_ 2418667135 S2P_Cfg13_SW_Ver_Byte14_63 "CSC软件版本号Byte14对应的ASCII码(国产MCU)";
CM_ SG_ 2418667135 S2P_Cfg13_SW_Ver_Byte15_63 "CSC软件版本号Byte15对应的ASCII码(国产MCU)";
CM_ SG_ 2418667135 S2P_Cfg13_SW_Ver_Byte16_63 "CSC软件版本号最高字节Byte16对应的ASCII码(国产MCU)";
CM_ SG_ 2483285649 E2P_Cfg1_SW_Ver_Byte1 "ETH软件版本字节1";
CM_ SG_ 2483285649 E2P_Cfg1_SW_Ver_Byte2 "ETH软件版本字节2";
CM_ SG_ 2483285649 E2P_Cfg1_SW_Ver_Byte3 "ETH软件版本字节3";
CM_ SG_ 2483285649 E2P_Cfg1_SW_Ver_Byte4 "ETH软件版本字节4";
CM_ SG_ 2483285649 E2P_Cfg1_SW_Ver_Byte5 "ETH软件版本字节5";
CM_ SG_ 2483285649 E2P_Cfg1_SW_Ver_Byte6 "ETH软件版本字节6";
CM_ SG_ 2483285649 E2P_Cfg1_SW_Ver_Byte7 "ETH软件版本字节7";
CM_ SG_ 2483285649 E2P_Cfg1_SW_Ver_Byte8 "ETH软件版本字节8";
CM_ SG_ 2483285650 E2P_Cfg1_SW_Ver_Byte1 "ETH软件版本字节1";
CM_ SG_ 2483285650 E2P_Cfg1_SW_Ver_Byte2 "ETH软件版本字节2";
CM_ SG_ 2483285650 E2P_Cfg1_SW_Ver_Byte3 "ETH软件版本字节3";
CM_ SG_ 2483285650 E2P_Cfg1_SW_Ver_Byte4 "ETH软件版本字节4";
CM_ SG_ 2483285650 E2P_Cfg1_SW_Ver_Byte5 "ETH软件版本字节5";
CM_ SG_ 2483285650 E2P_Cfg1_SW_Ver_Byte6 "ETH软件版本字节6";
CM_ SG_ 2483285650 E2P_Cfg1_SW_Ver_Byte7 "ETH软件版本字节7";
CM_ SG_ 2483285650 E2P_Cfg1_SW_Ver_Byte8 "ETH软件版本字节8";
CM_ SG_ 2483285651 E2P_Cfg1_SW_Ver_Byte1 "ETH软件版本字节1";
CM_ SG_ 2483285651 E2P_Cfg1_SW_Ver_Byte2 "ETH软件版本字节2";
CM_ SG_ 2483285651 E2P_Cfg1_SW_Ver_Byte3 "ETH软件版本字节3";
CM_ SG_ 2483285651 E2P_Cfg1_SW_Ver_Byte4 "ETH软件版本字节4";
CM_ SG_ 2483285651 E2P_Cfg1_SW_Ver_Byte5 "ETH软件版本字节5";
CM_ SG_ 2483285651 E2P_Cfg1_SW_Ver_Byte6 "ETH软件版本字节6";
CM_ SG_ 2483285651 E2P_Cfg1_SW_Ver_Byte7 "ETH软件版本字节7";
CM_ SG_ 2483285651 E2P_Cfg1_SW_Ver_Byte8 "ETH软件版本字节8";
CM_ SG_ 2483285652 E2P_Cfg1_SW_Ver_Byte1 "ETH软件版本字节1";
CM_ SG_ 2483285652 E2P_Cfg1_SW_Ver_Byte2 "ETH软件版本字节2";
CM_ SG_ 2483285652 E2P_Cfg1_SW_Ver_Byte3 "ETH软件版本字节3";
CM_ SG_ 2483285652 E2P_Cfg1_SW_Ver_Byte4 "ETH软件版本字节4";
CM_ SG_ 2483285652 E2P_Cfg1_SW_Ver_Byte5 "ETH软件版本字节5";
CM_ SG_ 2483285652 E2P_Cfg1_SW_Ver_Byte6 "ETH软件版本字节6";
CM_ SG_ 2483285652 E2P_Cfg1_SW_Ver_Byte7 "ETH软件版本字节7";
CM_ SG_ 2483285652 E2P_Cfg1_SW_Ver_Byte8 "ETH软件版本字节8";
CM_ SG_ 2483285653 E2P_Cfg1_SW_Ver_Byte1 "ETH软件版本字节1";
CM_ SG_ 2483285653 E2P_Cfg1_SW_Ver_Byte2 "ETH软件版本字节2";
CM_ SG_ 2483285653 E2P_Cfg1_SW_Ver_Byte3 "ETH软件版本字节3";
CM_ SG_ 2483285653 E2P_Cfg1_SW_Ver_Byte4 "ETH软件版本字节4";
CM_ SG_ 2483285653 E2P_Cfg1_SW_Ver_Byte5 "ETH软件版本字节5";
CM_ SG_ 2483285653 E2P_Cfg1_SW_Ver_Byte6 "ETH软件版本字节6";
CM_ SG_ 2483285653 E2P_Cfg1_SW_Ver_Byte7 "ETH软件版本字节7";
CM_ SG_ 2483285653 E2P_Cfg1_SW_Ver_Byte8 "ETH软件版本字节8";
CM_ SG_ 2483285654 E2P_Cfg1_SW_Ver_Byte1 "ETH软件版本字节1";
CM_ SG_ 2483285654 E2P_Cfg1_SW_Ver_Byte2 "ETH软件版本字节2";
CM_ SG_ 2483285654 E2P_Cfg1_SW_Ver_Byte3 "ETH软件版本字节3";
CM_ SG_ 2483285654 E2P_Cfg1_SW_Ver_Byte4 "ETH软件版本字节4";
CM_ SG_ 2483285654 E2P_Cfg1_SW_Ver_Byte5 "ETH软件版本字节5";
CM_ SG_ 2483285654 E2P_Cfg1_SW_Ver_Byte6 "ETH软件版本字节6";
CM_ SG_ 2483285654 E2P_Cfg1_SW_Ver_Byte7 "ETH软件版本字节7";
CM_ SG_ 2483285654 E2P_Cfg1_SW_Ver_Byte8 "ETH软件版本字节8";
CM_ SG_ 2483285655 E2P_Cfg1_SW_Ver_Byte1 "ETH软件版本字节1";
CM_ SG_ 2483285655 E2P_Cfg1_SW_Ver_Byte2 "ETH软件版本字节2";
CM_ SG_ 2483285655 E2P_Cfg1_SW_Ver_Byte3 "ETH软件版本字节3";
CM_ SG_ 2483285655 E2P_Cfg1_SW_Ver_Byte4 "ETH软件版本字节4";
CM_ SG_ 2483285655 E2P_Cfg1_SW_Ver_Byte5 "ETH软件版本字节5";
CM_ SG_ 2483285655 E2P_Cfg1_SW_Ver_Byte6 "ETH软件版本字节6";
CM_ SG_ 2483285655 E2P_Cfg1_SW_Ver_Byte7 "ETH软件版本字节7";
CM_ SG_ 2483285655 E2P_Cfg1_SW_Ver_Byte8 "ETH软件版本字节8";
CM_ SG_ 2483285656 E2P_Cfg1_SW_Ver_Byte1 "ETH软件版本字节1";
CM_ SG_ 2483285656 E2P_Cfg1_SW_Ver_Byte2 "ETH软件版本字节2";
CM_ SG_ 2483285656 E2P_Cfg1_SW_Ver_Byte3 "ETH软件版本字节3";
CM_ SG_ 2483285656 E2P_Cfg1_SW_Ver_Byte4 "ETH软件版本字节4";
CM_ SG_ 2483285656 E2P_Cfg1_SW_Ver_Byte5 "ETH软件版本字节5";
CM_ SG_ 2483285656 E2P_Cfg1_SW_Ver_Byte6 "ETH软件版本字节6";
CM_ SG_ 2483285656 E2P_Cfg1_SW_Ver_Byte7 "ETH软件版本字节7";
CM_ SG_ 2483285656 E2P_Cfg1_SW_Ver_Byte8 "ETH软件版本字节8";
CM_ SG_ 2483285657 E2P_Cfg1_SW_Ver_Byte1 "ETH软件版本字节1";
CM_ SG_ 2483285657 E2P_Cfg1_SW_Ver_Byte2 "ETH软件版本字节2";
CM_ SG_ 2483285657 E2P_Cfg1_SW_Ver_Byte3 "ETH软件版本字节3";
CM_ SG_ 2483285657 E2P_Cfg1_SW_Ver_Byte4 "ETH软件版本字节4";
CM_ SG_ 2483285657 E2P_Cfg1_SW_Ver_Byte5 "ETH软件版本字节5";
CM_ SG_ 2483285657 E2P_Cfg1_SW_Ver_Byte6 "ETH软件版本字节6";
CM_ SG_ 2483285657 E2P_Cfg1_SW_Ver_Byte7 "ETH软件版本字节7";
CM_ SG_ 2483285657 E2P_Cfg1_SW_Ver_Byte8 "ETH软件版本字节8";
CM_ SG_ 2483285658 E2P_Cfg1_SW_Ver_Byte1 "ETH软件版本字节1";
CM_ SG_ 2483285658 E2P_Cfg1_SW_Ver_Byte2 "ETH软件版本字节2";
CM_ SG_ 2483285658 E2P_Cfg1_SW_Ver_Byte3 "ETH软件版本字节3";
CM_ SG_ 2483285658 E2P_Cfg1_SW_Ver_Byte4 "ETH软件版本字节4";
CM_ SG_ 2483285658 E2P_Cfg1_SW_Ver_Byte5 "ETH软件版本字节5";
CM_ SG_ 2483285658 E2P_Cfg1_SW_Ver_Byte6 "ETH软件版本字节6";
CM_ SG_ 2483285658 E2P_Cfg1_SW_Ver_Byte7 "ETH软件版本字节7";
CM_ SG_ 2483285658 E2P_Cfg1_SW_Ver_Byte8 "ETH软件版本字节8";
CM_ SG_ 2483285659 E2P_Cfg1_SW_Ver_Byte1 "ETH软件版本字节1";
CM_ SG_ 2483285659 E2P_Cfg1_SW_Ver_Byte2 "ETH软件版本字节2";
CM_ SG_ 2483285659 E2P_Cfg1_SW_Ver_Byte3 "ETH软件版本字节3";
CM_ SG_ 2483285659 E2P_Cfg1_SW_Ver_Byte4 "ETH软件版本字节4";
CM_ SG_ 2483285659 E2P_Cfg1_SW_Ver_Byte5 "ETH软件版本字节5";
CM_ SG_ 2483285659 E2P_Cfg1_SW_Ver_Byte6 "ETH软件版本字节6";
CM_ SG_ 2483285659 E2P_Cfg1_SW_Ver_Byte7 "ETH软件版本字节7";
CM_ SG_ 2483285659 E2P_Cfg1_SW_Ver_Byte8 "ETH软件版本字节8";
CM_ SG_ 2483285660 E2P_Cfg1_SW_Ver_Byte1 "ETH软件版本字节1";
CM_ SG_ 2483285660 E2P_Cfg1_SW_Ver_Byte2 "ETH软件版本字节2";
CM_ SG_ 2483285660 E2P_Cfg1_SW_Ver_Byte3 "ETH软件版本字节3";
CM_ SG_ 2483285660 E2P_Cfg1_SW_Ver_Byte4 "ETH软件版本字节4";
CM_ SG_ 2483285660 E2P_Cfg1_SW_Ver_Byte5 "ETH软件版本字节5";
CM_ SG_ 2483285660 E2P_Cfg1_SW_Ver_Byte6 "ETH软件版本字节6";
CM_ SG_ 2483285660 E2P_Cfg1_SW_Ver_Byte7 "ETH软件版本字节7";
CM_ SG_ 2483285660 E2P_Cfg1_SW_Ver_Byte8 "ETH软件版本字节8";
CM_ SG_ 2483285661 E2P_Cfg1_SW_Ver_Byte1 "ETH软件版本字节1";
CM_ SG_ 2483285661 E2P_Cfg1_SW_Ver_Byte2 "ETH软件版本字节2";
CM_ SG_ 2483285661 E2P_Cfg1_SW_Ver_Byte3 "ETH软件版本字节3";
CM_ SG_ 2483285661 E2P_Cfg1_SW_Ver_Byte4 "ETH软件版本字节4";
CM_ SG_ 2483285661 E2P_Cfg1_SW_Ver_Byte5 "ETH软件版本字节5";
CM_ SG_ 2483285661 E2P_Cfg1_SW_Ver_Byte6 "ETH软件版本字节6";
CM_ SG_ 2483285661 E2P_Cfg1_SW_Ver_Byte7 "ETH软件版本字节7";
CM_ SG_ 2483285661 E2P_Cfg1_SW_Ver_Byte8 "ETH软件版本字节8";
CM_ SG_ 2483285662 E2P_Cfg1_SW_Ver_Byte1 "ETH软件版本字节1";
CM_ SG_ 2483285662 E2P_Cfg1_SW_Ver_Byte2 "ETH软件版本字节2";
CM_ SG_ 2483285662 E2P_Cfg1_SW_Ver_Byte3 "ETH软件版本字节3";
CM_ SG_ 2483285662 E2P_Cfg1_SW_Ver_Byte4 "ETH软件版本字节4";
CM_ SG_ 2483285662 E2P_Cfg1_SW_Ver_Byte5 "ETH软件版本字节5";
CM_ SG_ 2483285662 E2P_Cfg1_SW_Ver_Byte6 "ETH软件版本字节6";
CM_ SG_ 2483285662 E2P_Cfg1_SW_Ver_Byte7 "ETH软件版本字节7";
CM_ SG_ 2483285662 E2P_Cfg1_SW_Ver_Byte8 "ETH软件版本字节8";
CM_ SG_ 2483285663 E2P_Cfg1_SW_Ver_Byte1 "ETH软件版本字节1";
CM_ SG_ 2483285663 E2P_Cfg1_SW_Ver_Byte2 "ETH软件版本字节2";
CM_ SG_ 2483285663 E2P_Cfg1_SW_Ver_Byte3 "ETH软件版本字节3";
CM_ SG_ 2483285663 E2P_Cfg1_SW_Ver_Byte4 "ETH软件版本字节4";
CM_ SG_ 2483285663 E2P_Cfg1_SW_Ver_Byte5 "ETH软件版本字节5";
CM_ SG_ 2483285663 E2P_Cfg1_SW_Ver_Byte6 "ETH软件版本字节6";
CM_ SG_ 2483285663 E2P_Cfg1_SW_Ver_Byte7 "ETH软件版本字节7";
CM_ SG_ 2483285663 E2P_Cfg1_SW_Ver_Byte8 "ETH软件版本字节8";
CM_ SG_ 2483285664 E2P_Cfg1_SW_Ver_Byte1 "ETH软件版本字节1";
CM_ SG_ 2483285664 E2P_Cfg1_SW_Ver_Byte2 "ETH软件版本字节2";
CM_ SG_ 2483285664 E2P_Cfg1_SW_Ver_Byte3 "ETH软件版本字节3";
CM_ SG_ 2483285664 E2P_Cfg1_SW_Ver_Byte4 "ETH软件版本字节4";
CM_ SG_ 2483285664 E2P_Cfg1_SW_Ver_Byte5 "ETH软件版本字节5";
CM_ SG_ 2483285664 E2P_Cfg1_SW_Ver_Byte6 "ETH软件版本字节6";
CM_ SG_ 2483285664 E2P_Cfg1_SW_Ver_Byte7 "ETH软件版本字节7";
CM_ SG_ 2483285664 E2P_Cfg1_SW_Ver_Byte8 "ETH软件版本字节8";
CM_ SG_ 2483285665 E2P_Cfg1_SW_Ver_Byte1 "ETH软件版本字节1";
CM_ SG_ 2483285665 E2P_Cfg1_SW_Ver_Byte2 "ETH软件版本字节2";
CM_ SG_ 2483285665 E2P_Cfg1_SW_Ver_Byte3 "ETH软件版本字节3";
CM_ SG_ 2483285665 E2P_Cfg1_SW_Ver_Byte4 "ETH软件版本字节4";
CM_ SG_ 2483285665 E2P_Cfg1_SW_Ver_Byte5 "ETH软件版本字节5";
CM_ SG_ 2483285665 E2P_Cfg1_SW_Ver_Byte6 "ETH软件版本字节6";
CM_ SG_ 2483285665 E2P_Cfg1_SW_Ver_Byte7 "ETH软件版本字节7";
CM_ SG_ 2483285665 E2P_Cfg1_SW_Ver_Byte8 "ETH软件版本字节8";
CM_ SG_ 2483285666 E2P_Cfg1_SW_Ver_Byte1 "ETH软件版本字节1";
CM_ SG_ 2483285666 E2P_Cfg1_SW_Ver_Byte2 "ETH软件版本字节2";
CM_ SG_ 2483285666 E2P_Cfg1_SW_Ver_Byte3 "ETH软件版本字节3";
CM_ SG_ 2483285666 E2P_Cfg1_SW_Ver_Byte4 "ETH软件版本字节4";
CM_ SG_ 2483285666 E2P_Cfg1_SW_Ver_Byte5 "ETH软件版本字节5";
CM_ SG_ 2483285666 E2P_Cfg1_SW_Ver_Byte6 "ETH软件版本字节6";
CM_ SG_ 2483285666 E2P_Cfg1_SW_Ver_Byte7 "ETH软件版本字节7";
CM_ SG_ 2483285666 E2P_Cfg1_SW_Ver_Byte8 "ETH软件版本字节8";
CM_ SG_ 2483285667 E2P_Cfg1_SW_Ver_Byte1 "ETH软件版本字节1";
CM_ SG_ 2483285667 E2P_Cfg1_SW_Ver_Byte2 "ETH软件版本字节2";
CM_ SG_ 2483285667 E2P_Cfg1_SW_Ver_Byte3 "ETH软件版本字节3";
CM_ SG_ 2483285667 E2P_Cfg1_SW_Ver_Byte4 "ETH软件版本字节4";
CM_ SG_ 2483285667 E2P_Cfg1_SW_Ver_Byte5 "ETH软件版本字节5";
CM_ SG_ 2483285667 E2P_Cfg1_SW_Ver_Byte6 "ETH软件版本字节6";
CM_ SG_ 2483285667 E2P_Cfg1_SW_Ver_Byte7 "ETH软件版本字节7";
CM_ SG_ 2483285667 E2P_Cfg1_SW_Ver_Byte8 "ETH软件版本字节8";
CM_ SG_ 2483285668 E2P_Cfg1_SW_Ver_Byte1 "ETH软件版本字节1";
CM_ SG_ 2483285668 E2P_Cfg1_SW_Ver_Byte2 "ETH软件版本字节2";
CM_ SG_ 2483285668 E2P_Cfg1_SW_Ver_Byte3 "ETH软件版本字节3";
CM_ SG_ 2483285668 E2P_Cfg1_SW_Ver_Byte4 "ETH软件版本字节4";
CM_ SG_ 2483285668 E2P_Cfg1_SW_Ver_Byte5 "ETH软件版本字节5";
CM_ SG_ 2483285668 E2P_Cfg1_SW_Ver_Byte6 "ETH软件版本字节6";
CM_ SG_ 2483285668 E2P_Cfg1_SW_Ver_Byte7 "ETH软件版本字节7";
CM_ SG_ 2483285668 E2P_Cfg1_SW_Ver_Byte8 "ETH软件版本字节8";
CM_ SG_ 2483285669 E2P_Cfg1_SW_Ver_Byte1 "ETH软件版本字节1";
CM_ SG_ 2483285669 E2P_Cfg1_SW_Ver_Byte2 "ETH软件版本字节2";
CM_ SG_ 2483285669 E2P_Cfg1_SW_Ver_Byte3 "ETH软件版本字节3";
CM_ SG_ 2483285669 E2P_Cfg1_SW_Ver_Byte4 "ETH软件版本字节4";
CM_ SG_ 2483285669 E2P_Cfg1_SW_Ver_Byte5 "ETH软件版本字节5";
CM_ SG_ 2483285669 E2P_Cfg1_SW_Ver_Byte6 "ETH软件版本字节6";
CM_ SG_ 2483285669 E2P_Cfg1_SW_Ver_Byte7 "ETH软件版本字节7";
CM_ SG_ 2483285669 E2P_Cfg1_SW_Ver_Byte8 "ETH软件版本字节8";
CM_ SG_ 2483285670 E2P_Cfg1_SW_Ver_Byte1 "ETH软件版本字节1";
CM_ SG_ 2483285670 E2P_Cfg1_SW_Ver_Byte2 "ETH软件版本字节2";
CM_ SG_ 2483285670 E2P_Cfg1_SW_Ver_Byte3 "ETH软件版本字节3";
CM_ SG_ 2483285670 E2P_Cfg1_SW_Ver_Byte4 "ETH软件版本字节4";
CM_ SG_ 2483285670 E2P_Cfg1_SW_Ver_Byte5 "ETH软件版本字节5";
CM_ SG_ 2483285670 E2P_Cfg1_SW_Ver_Byte6 "ETH软件版本字节6";
CM_ SG_ 2483285670 E2P_Cfg1_SW_Ver_Byte7 "ETH软件版本字节7";
CM_ SG_ 2483285670 E2P_Cfg1_SW_Ver_Byte8 "ETH软件版本字节8";
CM_ SG_ 2483285671 E2P_Cfg1_SW_Ver_Byte1 "ETH软件版本字节1";
CM_ SG_ 2483285671 E2P_Cfg1_SW_Ver_Byte2 "ETH软件版本字节2";
CM_ SG_ 2483285671 E2P_Cfg1_SW_Ver_Byte3 "ETH软件版本字节3";
CM_ SG_ 2483285671 E2P_Cfg1_SW_Ver_Byte4 "ETH软件版本字节4";
CM_ SG_ 2483285671 E2P_Cfg1_SW_Ver_Byte5 "ETH软件版本字节5";
CM_ SG_ 2483285671 E2P_Cfg1_SW_Ver_Byte6 "ETH软件版本字节6";
CM_ SG_ 2483285671 E2P_Cfg1_SW_Ver_Byte7 "ETH软件版本字节7";
CM_ SG_ 2483285671 E2P_Cfg1_SW_Ver_Byte8 "ETH软件版本字节8";
CM_ SG_ 2483285672 E2P_Cfg1_SW_Ver_Byte1 "ETH软件版本字节1";
CM_ SG_ 2483285672 E2P_Cfg1_SW_Ver_Byte2 "ETH软件版本字节2";
CM_ SG_ 2483285672 E2P_Cfg1_SW_Ver_Byte3 "ETH软件版本字节3";
CM_ SG_ 2483285672 E2P_Cfg1_SW_Ver_Byte4 "ETH软件版本字节4";
CM_ SG_ 2483285672 E2P_Cfg1_SW_Ver_Byte5 "ETH软件版本字节5";
CM_ SG_ 2483285672 E2P_Cfg1_SW_Ver_Byte6 "ETH软件版本字节6";
CM_ SG_ 2483285672 E2P_Cfg1_SW_Ver_Byte7 "ETH软件版本字节7";
CM_ SG_ 2483285672 E2P_Cfg1_SW_Ver_Byte8 "ETH软件版本字节8";
CM_ SG_ 2483285673 E2P_Cfg1_SW_Ver_Byte1 "ETH软件版本字节1";
CM_ SG_ 2483285673 E2P_Cfg1_SW_Ver_Byte2 "ETH软件版本字节2";
CM_ SG_ 2483285673 E2P_Cfg1_SW_Ver_Byte3 "ETH软件版本字节3";
CM_ SG_ 2483285673 E2P_Cfg1_SW_Ver_Byte4 "ETH软件版本字节4";
CM_ SG_ 2483285673 E2P_Cfg1_SW_Ver_Byte5 "ETH软件版本字节5";
CM_ SG_ 2483285673 E2P_Cfg1_SW_Ver_Byte6 "ETH软件版本字节6";
CM_ SG_ 2483285673 E2P_Cfg1_SW_Ver_Byte7 "ETH软件版本字节7";
CM_ SG_ 2483285673 E2P_Cfg1_SW_Ver_Byte8 "ETH软件版本字节8";
CM_ SG_ 2483285674 E2P_Cfg1_SW_Ver_Byte1 "ETH软件版本字节1";
CM_ SG_ 2483285674 E2P_Cfg1_SW_Ver_Byte2 "ETH软件版本字节2";
CM_ SG_ 2483285674 E2P_Cfg1_SW_Ver_Byte3 "ETH软件版本字节3";
CM_ SG_ 2483285674 E2P_Cfg1_SW_Ver_Byte4 "ETH软件版本字节4";
CM_ SG_ 2483285674 E2P_Cfg1_SW_Ver_Byte5 "ETH软件版本字节5";
CM_ SG_ 2483285674 E2P_Cfg1_SW_Ver_Byte6 "ETH软件版本字节6";
CM_ SG_ 2483285674 E2P_Cfg1_SW_Ver_Byte7 "ETH软件版本字节7";
CM_ SG_ 2483285674 E2P_Cfg1_SW_Ver_Byte8 "ETH软件版本字节8";
CM_ SG_ 2483285675 E2P_Cfg1_SW_Ver_Byte1 "ETH软件版本字节1";
CM_ SG_ 2483285675 E2P_Cfg1_SW_Ver_Byte2 "ETH软件版本字节2";
CM_ SG_ 2483285675 E2P_Cfg1_SW_Ver_Byte3 "ETH软件版本字节3";
CM_ SG_ 2483285675 E2P_Cfg1_SW_Ver_Byte4 "ETH软件版本字节4";
CM_ SG_ 2483285675 E2P_Cfg1_SW_Ver_Byte5 "ETH软件版本字节5";
CM_ SG_ 2483285675 E2P_Cfg1_SW_Ver_Byte6 "ETH软件版本字节6";
CM_ SG_ 2483285675 E2P_Cfg1_SW_Ver_Byte7 "ETH软件版本字节7";
CM_ SG_ 2483285675 E2P_Cfg1_SW_Ver_Byte8 "ETH软件版本字节8";
CM_ SG_ 2483285676 E2P_Cfg1_SW_Ver_Byte1 "ETH软件版本字节1";
CM_ SG_ 2483285676 E2P_Cfg1_SW_Ver_Byte2 "ETH软件版本字节2";
CM_ SG_ 2483285676 E2P_Cfg1_SW_Ver_Byte3 "ETH软件版本字节3";
CM_ SG_ 2483285676 E2P_Cfg1_SW_Ver_Byte4 "ETH软件版本字节4";
CM_ SG_ 2483285676 E2P_Cfg1_SW_Ver_Byte5 "ETH软件版本字节5";
CM_ SG_ 2483285676 E2P_Cfg1_SW_Ver_Byte6 "ETH软件版本字节6";
CM_ SG_ 2483285676 E2P_Cfg1_SW_Ver_Byte7 "ETH软件版本字节7";
CM_ SG_ 2483285676 E2P_Cfg1_SW_Ver_Byte8 "ETH软件版本字节8";
CM_ SG_ 2483285677 E2P_Cfg1_SW_Ver_Byte1 "ETH软件版本字节1";
CM_ SG_ 2483285677 E2P_Cfg1_SW_Ver_Byte2 "ETH软件版本字节2";
CM_ SG_ 2483285677 E2P_Cfg1_SW_Ver_Byte3 "ETH软件版本字节3";
CM_ SG_ 2483285677 E2P_Cfg1_SW_Ver_Byte4 "ETH软件版本字节4";
CM_ SG_ 2483285677 E2P_Cfg1_SW_Ver_Byte5 "ETH软件版本字节5";
CM_ SG_ 2483285677 E2P_Cfg1_SW_Ver_Byte6 "ETH软件版本字节6";
CM_ SG_ 2483285677 E2P_Cfg1_SW_Ver_Byte7 "ETH软件版本字节7";
CM_ SG_ 2483285677 E2P_Cfg1_SW_Ver_Byte8 "ETH软件版本字节8";
CM_ SG_ 2483285678 E2P_Cfg1_SW_Ver_Byte1 "ETH软件版本字节1";
CM_ SG_ 2483285678 E2P_Cfg1_SW_Ver_Byte2 "ETH软件版本字节2";
CM_ SG_ 2483285678 E2P_Cfg1_SW_Ver_Byte3 "ETH软件版本字节3";
CM_ SG_ 2483285678 E2P_Cfg1_SW_Ver_Byte4 "ETH软件版本字节4";
CM_ SG_ 2483285678 E2P_Cfg1_SW_Ver_Byte5 "ETH软件版本字节5";
CM_ SG_ 2483285678 E2P_Cfg1_SW_Ver_Byte6 "ETH软件版本字节6";
CM_ SG_ 2483285678 E2P_Cfg1_SW_Ver_Byte7 "ETH软件版本字节7";
CM_ SG_ 2483285678 E2P_Cfg1_SW_Ver_Byte8 "ETH软件版本字节8";
CM_ SG_ 2483285679 E2P_Cfg1_SW_Ver_Byte1 "ETH软件版本字节1";
CM_ SG_ 2483285679 E2P_Cfg1_SW_Ver_Byte2 "ETH软件版本字节2";
CM_ SG_ 2483285679 E2P_Cfg1_SW_Ver_Byte3 "ETH软件版本字节3";
CM_ SG_ 2483285679 E2P_Cfg1_SW_Ver_Byte4 "ETH软件版本字节4";
CM_ SG_ 2483285679 E2P_Cfg1_SW_Ver_Byte5 "ETH软件版本字节5";
CM_ SG_ 2483285679 E2P_Cfg1_SW_Ver_Byte6 "ETH软件版本字节6";
CM_ SG_ 2483285679 E2P_Cfg1_SW_Ver_Byte7 "ETH软件版本字节7";
CM_ SG_ 2483285679 E2P_Cfg1_SW_Ver_Byte8 "ETH软件版本字节8";
CM_ SG_ 2483351185 E2P_Cfg2_SW_Ver_Byte9 "ETH软件版本字节9";
CM_ SG_ 2483351185 E2P_Cfg2_SW_Ver_Byte10 "ETH软件版本字节10";
CM_ SG_ 2483351185 E2P_Cfg2_SW_Ver_Byte11 "ETH软件版本字节11";
CM_ SG_ 2483351185 E2P_Cfg2_SW_Ver_Byte12 "ETH软件版本字节12";
CM_ SG_ 2483351185 E2P_Cfg2_SW_Ver_Byte13 "ETH软件版本字节13";
CM_ SG_ 2483351185 E2P_Cfg2_SW_Ver_Byte14 "ETH软件版本字节14";
CM_ SG_ 2483351185 E2P_Cfg2_SW_Ver_Byte15 "ETH软件版本字节15";
CM_ SG_ 2483351185 E2P_Cfg2_SW_Ver_Byte16 "ETH软件版本字节16";
CM_ SG_ 2483351186 E2P_Cfg2_SW_Ver_Byte9 "ETH软件版本字节9";
CM_ SG_ 2483351186 E2P_Cfg2_SW_Ver_Byte10 "ETH软件版本字节10";
CM_ SG_ 2483351186 E2P_Cfg2_SW_Ver_Byte11 "ETH软件版本字节11";
CM_ SG_ 2483351186 E2P_Cfg2_SW_Ver_Byte12 "ETH软件版本字节12";
CM_ SG_ 2483351186 E2P_Cfg2_SW_Ver_Byte13 "ETH软件版本字节13";
CM_ SG_ 2483351186 E2P_Cfg2_SW_Ver_Byte14 "ETH软件版本字节14";
CM_ SG_ 2483351186 E2P_Cfg2_SW_Ver_Byte15 "ETH软件版本字节15";
CM_ SG_ 2483351186 E2P_Cfg2_SW_Ver_Byte16 "ETH软件版本字节16";
CM_ SG_ 2483351187 E2P_Cfg2_SW_Ver_Byte9 "ETH软件版本字节9";
CM_ SG_ 2483351187 E2P_Cfg2_SW_Ver_Byte10 "ETH软件版本字节10";
CM_ SG_ 2483351187 E2P_Cfg2_SW_Ver_Byte11 "ETH软件版本字节11";
CM_ SG_ 2483351187 E2P_Cfg2_SW_Ver_Byte12 "ETH软件版本字节12";
CM_ SG_ 2483351187 E2P_Cfg2_SW_Ver_Byte13 "ETH软件版本字节13";
CM_ SG_ 2483351187 E2P_Cfg2_SW_Ver_Byte14 "ETH软件版本字节14";
CM_ SG_ 2483351187 E2P_Cfg2_SW_Ver_Byte15 "ETH软件版本字节15";
CM_ SG_ 2483351187 E2P_Cfg2_SW_Ver_Byte16 "ETH软件版本字节16";
CM_ SG_ 2483351188 E2P_Cfg2_SW_Ver_Byte9 "ETH软件版本字节9";
CM_ SG_ 2483351188 E2P_Cfg2_SW_Ver_Byte10 "ETH软件版本字节10";
CM_ SG_ 2483351188 E2P_Cfg2_SW_Ver_Byte11 "ETH软件版本字节11";
CM_ SG_ 2483351188 E2P_Cfg2_SW_Ver_Byte12 "ETH软件版本字节12";
CM_ SG_ 2483351188 E2P_Cfg2_SW_Ver_Byte13 "ETH软件版本字节13";
CM_ SG_ 2483351188 E2P_Cfg2_SW_Ver_Byte14 "ETH软件版本字节14";
CM_ SG_ 2483351188 E2P_Cfg2_SW_Ver_Byte15 "ETH软件版本字节15";
CM_ SG_ 2483351188 E2P_Cfg2_SW_Ver_Byte16 "ETH软件版本字节16";
CM_ SG_ 2483351189 E2P_Cfg2_SW_Ver_Byte9 "ETH软件版本字节9";
CM_ SG_ 2483351189 E2P_Cfg2_SW_Ver_Byte10 "ETH软件版本字节10";
CM_ SG_ 2483351189 E2P_Cfg2_SW_Ver_Byte11 "ETH软件版本字节11";
CM_ SG_ 2483351189 E2P_Cfg2_SW_Ver_Byte12 "ETH软件版本字节12";
CM_ SG_ 2483351189 E2P_Cfg2_SW_Ver_Byte13 "ETH软件版本字节13";
CM_ SG_ 2483351189 E2P_Cfg2_SW_Ver_Byte14 "ETH软件版本字节14";
CM_ SG_ 2483351189 E2P_Cfg2_SW_Ver_Byte15 "ETH软件版本字节15";
CM_ SG_ 2483351189 E2P_Cfg2_SW_Ver_Byte16 "ETH软件版本字节16";
CM_ SG_ 2483351190 E2P_Cfg2_SW_Ver_Byte9 "ETH软件版本字节9";
CM_ SG_ 2483351190 E2P_Cfg2_SW_Ver_Byte10 "ETH软件版本字节10";
CM_ SG_ 2483351190 E2P_Cfg2_SW_Ver_Byte11 "ETH软件版本字节11";
CM_ SG_ 2483351190 E2P_Cfg2_SW_Ver_Byte12 "ETH软件版本字节12";
CM_ SG_ 2483351190 E2P_Cfg2_SW_Ver_Byte13 "ETH软件版本字节13";
CM_ SG_ 2483351190 E2P_Cfg2_SW_Ver_Byte14 "ETH软件版本字节14";
CM_ SG_ 2483351190 E2P_Cfg2_SW_Ver_Byte15 "ETH软件版本字节15";
CM_ SG_ 2483351190 E2P_Cfg2_SW_Ver_Byte16 "ETH软件版本字节16";
CM_ SG_ 2483351191 E2P_Cfg2_SW_Ver_Byte9 "ETH软件版本字节9";
CM_ SG_ 2483351191 E2P_Cfg2_SW_Ver_Byte10 "ETH软件版本字节10";
CM_ SG_ 2483351191 E2P_Cfg2_SW_Ver_Byte11 "ETH软件版本字节11";
CM_ SG_ 2483351191 E2P_Cfg2_SW_Ver_Byte12 "ETH软件版本字节12";
CM_ SG_ 2483351191 E2P_Cfg2_SW_Ver_Byte13 "ETH软件版本字节13";
CM_ SG_ 2483351191 E2P_Cfg2_SW_Ver_Byte14 "ETH软件版本字节14";
CM_ SG_ 2483351191 E2P_Cfg2_SW_Ver_Byte15 "ETH软件版本字节15";
CM_ SG_ 2483351191 E2P_Cfg2_SW_Ver_Byte16 "ETH软件版本字节16";
CM_ SG_ 2483351192 E2P_Cfg2_SW_Ver_Byte9 "ETH软件版本字节9";
CM_ SG_ 2483351192 E2P_Cfg2_SW_Ver_Byte10 "ETH软件版本字节10";
CM_ SG_ 2483351192 E2P_Cfg2_SW_Ver_Byte11 "ETH软件版本字节11";
CM_ SG_ 2483351192 E2P_Cfg2_SW_Ver_Byte12 "ETH软件版本字节12";
CM_ SG_ 2483351192 E2P_Cfg2_SW_Ver_Byte13 "ETH软件版本字节13";
CM_ SG_ 2483351192 E2P_Cfg2_SW_Ver_Byte14 "ETH软件版本字节14";
CM_ SG_ 2483351192 E2P_Cfg2_SW_Ver_Byte15 "ETH软件版本字节15";
CM_ SG_ 2483351192 E2P_Cfg2_SW_Ver_Byte16 "ETH软件版本字节16";
CM_ SG_ 2483351193 E2P_Cfg2_SW_Ver_Byte9 "ETH软件版本字节9";
CM_ SG_ 2483351193 E2P_Cfg2_SW_Ver_Byte10 "ETH软件版本字节10";
CM_ SG_ 2483351193 E2P_Cfg2_SW_Ver_Byte11 "ETH软件版本字节11";
CM_ SG_ 2483351193 E2P_Cfg2_SW_Ver_Byte12 "ETH软件版本字节12";
CM_ SG_ 2483351193 E2P_Cfg2_SW_Ver_Byte13 "ETH软件版本字节13";
CM_ SG_ 2483351193 E2P_Cfg2_SW_Ver_Byte14 "ETH软件版本字节14";
CM_ SG_ 2483351193 E2P_Cfg2_SW_Ver_Byte15 "ETH软件版本字节15";
CM_ SG_ 2483351193 E2P_Cfg2_SW_Ver_Byte16 "ETH软件版本字节16";
CM_ SG_ 2483351194 E2P_Cfg2_SW_Ver_Byte9 "ETH软件版本字节9";
CM_ SG_ 2483351194 E2P_Cfg2_SW_Ver_Byte10 "ETH软件版本字节10";
CM_ SG_ 2483351194 E2P_Cfg2_SW_Ver_Byte11 "ETH软件版本字节11";
CM_ SG_ 2483351194 E2P_Cfg2_SW_Ver_Byte12 "ETH软件版本字节12";
CM_ SG_ 2483351194 E2P_Cfg2_SW_Ver_Byte13 "ETH软件版本字节13";
CM_ SG_ 2483351194 E2P_Cfg2_SW_Ver_Byte14 "ETH软件版本字节14";
CM_ SG_ 2483351194 E2P_Cfg2_SW_Ver_Byte15 "ETH软件版本字节15";
CM_ SG_ 2483351194 E2P_Cfg2_SW_Ver_Byte16 "ETH软件版本字节16";
CM_ SG_ 2483351195 E2P_Cfg2_SW_Ver_Byte9 "ETH软件版本字节9";
CM_ SG_ 2483351195 E2P_Cfg2_SW_Ver_Byte10 "ETH软件版本字节10";
CM_ SG_ 2483351195 E2P_Cfg2_SW_Ver_Byte11 "ETH软件版本字节11";
CM_ SG_ 2483351195 E2P_Cfg2_SW_Ver_Byte12 "ETH软件版本字节12";
CM_ SG_ 2483351195 E2P_Cfg2_SW_Ver_Byte13 "ETH软件版本字节13";
CM_ SG_ 2483351195 E2P_Cfg2_SW_Ver_Byte14 "ETH软件版本字节14";
CM_ SG_ 2483351195 E2P_Cfg2_SW_Ver_Byte15 "ETH软件版本字节15";
CM_ SG_ 2483351195 E2P_Cfg2_SW_Ver_Byte16 "ETH软件版本字节16";
CM_ SG_ 2483351196 E2P_Cfg2_SW_Ver_Byte9 "ETH软件版本字节9";
CM_ SG_ 2483351196 E2P_Cfg2_SW_Ver_Byte10 "ETH软件版本字节10";
CM_ SG_ 2483351196 E2P_Cfg2_SW_Ver_Byte11 "ETH软件版本字节11";
CM_ SG_ 2483351196 E2P_Cfg2_SW_Ver_Byte12 "ETH软件版本字节12";
CM_ SG_ 2483351196 E2P_Cfg2_SW_Ver_Byte13 "ETH软件版本字节13";
CM_ SG_ 2483351196 E2P_Cfg2_SW_Ver_Byte14 "ETH软件版本字节14";
CM_ SG_ 2483351196 E2P_Cfg2_SW_Ver_Byte15 "ETH软件版本字节15";
CM_ SG_ 2483351196 E2P_Cfg2_SW_Ver_Byte16 "ETH软件版本字节16";
CM_ SG_ 2483351197 E2P_Cfg2_SW_Ver_Byte9 "ETH软件版本字节9";
CM_ SG_ 2483351197 E2P_Cfg2_SW_Ver_Byte10 "ETH软件版本字节10";
CM_ SG_ 2483351197 E2P_Cfg2_SW_Ver_Byte11 "ETH软件版本字节11";
CM_ SG_ 2483351197 E2P_Cfg2_SW_Ver_Byte12 "ETH软件版本字节12";
CM_ SG_ 2483351197 E2P_Cfg2_SW_Ver_Byte13 "ETH软件版本字节13";
CM_ SG_ 2483351197 E2P_Cfg2_SW_Ver_Byte14 "ETH软件版本字节14";
CM_ SG_ 2483351197 E2P_Cfg2_SW_Ver_Byte15 "ETH软件版本字节15";
CM_ SG_ 2483351197 E2P_Cfg2_SW_Ver_Byte16 "ETH软件版本字节16";
CM_ SG_ 2483351198 E2P_Cfg2_SW_Ver_Byte9 "ETH软件版本字节9";
CM_ SG_ 2483351198 E2P_Cfg2_SW_Ver_Byte10 "ETH软件版本字节10";
CM_ SG_ 2483351198 E2P_Cfg2_SW_Ver_Byte11 "ETH软件版本字节11";
CM_ SG_ 2483351198 E2P_Cfg2_SW_Ver_Byte12 "ETH软件版本字节12";
CM_ SG_ 2483351198 E2P_Cfg2_SW_Ver_Byte13 "ETH软件版本字节13";
CM_ SG_ 2483351198 E2P_Cfg2_SW_Ver_Byte14 "ETH软件版本字节14";
CM_ SG_ 2483351198 E2P_Cfg2_SW_Ver_Byte15 "ETH软件版本字节15";
CM_ SG_ 2483351198 E2P_Cfg2_SW_Ver_Byte16 "ETH软件版本字节16";
CM_ SG_ 2483351199 E2P_Cfg2_SW_Ver_Byte9 "ETH软件版本字节9";
CM_ SG_ 2483351199 E2P_Cfg2_SW_Ver_Byte10 "ETH软件版本字节10";
CM_ SG_ 2483351199 E2P_Cfg2_SW_Ver_Byte11 "ETH软件版本字节11";
CM_ SG_ 2483351199 E2P_Cfg2_SW_Ver_Byte12 "ETH软件版本字节12";
CM_ SG_ 2483351199 E2P_Cfg2_SW_Ver_Byte13 "ETH软件版本字节13";
CM_ SG_ 2483351199 E2P_Cfg2_SW_Ver_Byte14 "ETH软件版本字节14";
CM_ SG_ 2483351199 E2P_Cfg2_SW_Ver_Byte15 "ETH软件版本字节15";
CM_ SG_ 2483351199 E2P_Cfg2_SW_Ver_Byte16 "ETH软件版本字节16";
CM_ SG_ 2483351200 E2P_Cfg2_SW_Ver_Byte9 "ETH软件版本字节9";
CM_ SG_ 2483351200 E2P_Cfg2_SW_Ver_Byte10 "ETH软件版本字节10";
CM_ SG_ 2483351200 E2P_Cfg2_SW_Ver_Byte11 "ETH软件版本字节11";
CM_ SG_ 2483351200 E2P_Cfg2_SW_Ver_Byte12 "ETH软件版本字节12";
CM_ SG_ 2483351200 E2P_Cfg2_SW_Ver_Byte13 "ETH软件版本字节13";
CM_ SG_ 2483351200 E2P_Cfg2_SW_Ver_Byte14 "ETH软件版本字节14";
CM_ SG_ 2483351200 E2P_Cfg2_SW_Ver_Byte15 "ETH软件版本字节15";
CM_ SG_ 2483351200 E2P_Cfg2_SW_Ver_Byte16 "ETH软件版本字节16";
CM_ SG_ 2483351201 E2P_Cfg2_SW_Ver_Byte9 "ETH软件版本字节9";
CM_ SG_ 2483351201 E2P_Cfg2_SW_Ver_Byte10 "ETH软件版本字节10";
CM_ SG_ 2483351201 E2P_Cfg2_SW_Ver_Byte11 "ETH软件版本字节11";
CM_ SG_ 2483351201 E2P_Cfg2_SW_Ver_Byte12 "ETH软件版本字节12";
CM_ SG_ 2483351201 E2P_Cfg2_SW_Ver_Byte13 "ETH软件版本字节13";
CM_ SG_ 2483351201 E2P_Cfg2_SW_Ver_Byte14 "ETH软件版本字节14";
CM_ SG_ 2483351201 E2P_Cfg2_SW_Ver_Byte15 "ETH软件版本字节15";
CM_ SG_ 2483351201 E2P_Cfg2_SW_Ver_Byte16 "ETH软件版本字节16";
CM_ SG_ 2483351202 E2P_Cfg2_SW_Ver_Byte9 "ETH软件版本字节9";
CM_ SG_ 2483351202 E2P_Cfg2_SW_Ver_Byte10 "ETH软件版本字节10";
CM_ SG_ 2483351202 E2P_Cfg2_SW_Ver_Byte11 "ETH软件版本字节11";
CM_ SG_ 2483351202 E2P_Cfg2_SW_Ver_Byte12 "ETH软件版本字节12";
CM_ SG_ 2483351202 E2P_Cfg2_SW_Ver_Byte13 "ETH软件版本字节13";
CM_ SG_ 2483351202 E2P_Cfg2_SW_Ver_Byte14 "ETH软件版本字节14";
CM_ SG_ 2483351202 E2P_Cfg2_SW_Ver_Byte15 "ETH软件版本字节15";
CM_ SG_ 2483351202 E2P_Cfg2_SW_Ver_Byte16 "ETH软件版本字节16";
CM_ SG_ 2483351203 E2P_Cfg2_SW_Ver_Byte9 "ETH软件版本字节9";
CM_ SG_ 2483351203 E2P_Cfg2_SW_Ver_Byte10 "ETH软件版本字节10";
CM_ SG_ 2483351203 E2P_Cfg2_SW_Ver_Byte11 "ETH软件版本字节11";
CM_ SG_ 2483351203 E2P_Cfg2_SW_Ver_Byte12 "ETH软件版本字节12";
CM_ SG_ 2483351203 E2P_Cfg2_SW_Ver_Byte13 "ETH软件版本字节13";
CM_ SG_ 2483351203 E2P_Cfg2_SW_Ver_Byte14 "ETH软件版本字节14";
CM_ SG_ 2483351203 E2P_Cfg2_SW_Ver_Byte15 "ETH软件版本字节15";
CM_ SG_ 2483351203 E2P_Cfg2_SW_Ver_Byte16 "ETH软件版本字节16";
CM_ SG_ 2483351204 E2P_Cfg2_SW_Ver_Byte9 "ETH软件版本字节9";
CM_ SG_ 2483351204 E2P_Cfg2_SW_Ver_Byte10 "ETH软件版本字节10";
CM_ SG_ 2483351204 E2P_Cfg2_SW_Ver_Byte11 "ETH软件版本字节11";
CM_ SG_ 2483351204 E2P_Cfg2_SW_Ver_Byte12 "ETH软件版本字节12";
CM_ SG_ 2483351204 E2P_Cfg2_SW_Ver_Byte13 "ETH软件版本字节13";
CM_ SG_ 2483351204 E2P_Cfg2_SW_Ver_Byte14 "ETH软件版本字节14";
CM_ SG_ 2483351204 E2P_Cfg2_SW_Ver_Byte15 "ETH软件版本字节15";
CM_ SG_ 2483351204 E2P_Cfg2_SW_Ver_Byte16 "ETH软件版本字节16";
CM_ SG_ 2483351205 E2P_Cfg2_SW_Ver_Byte9 "ETH软件版本字节9";
CM_ SG_ 2483351205 E2P_Cfg2_SW_Ver_Byte10 "ETH软件版本字节10";
CM_ SG_ 2483351205 E2P_Cfg2_SW_Ver_Byte11 "ETH软件版本字节11";
CM_ SG_ 2483351205 E2P_Cfg2_SW_Ver_Byte12 "ETH软件版本字节12";
CM_ SG_ 2483351205 E2P_Cfg2_SW_Ver_Byte13 "ETH软件版本字节13";
CM_ SG_ 2483351205 E2P_Cfg2_SW_Ver_Byte14 "ETH软件版本字节14";
CM_ SG_ 2483351205 E2P_Cfg2_SW_Ver_Byte15 "ETH软件版本字节15";
CM_ SG_ 2483351205 E2P_Cfg2_SW_Ver_Byte16 "ETH软件版本字节16";
CM_ SG_ 2483351206 E2P_Cfg2_SW_Ver_Byte9 "ETH软件版本字节9";
CM_ SG_ 2483351206 E2P_Cfg2_SW_Ver_Byte10 "ETH软件版本字节10";
CM_ SG_ 2483351206 E2P_Cfg2_SW_Ver_Byte11 "ETH软件版本字节11";
CM_ SG_ 2483351206 E2P_Cfg2_SW_Ver_Byte12 "ETH软件版本字节12";
CM_ SG_ 2483351206 E2P_Cfg2_SW_Ver_Byte13 "ETH软件版本字节13";
CM_ SG_ 2483351206 E2P_Cfg2_SW_Ver_Byte14 "ETH软件版本字节14";
CM_ SG_ 2483351206 E2P_Cfg2_SW_Ver_Byte15 "ETH软件版本字节15";
CM_ SG_ 2483351206 E2P_Cfg2_SW_Ver_Byte16 "ETH软件版本字节16";
CM_ SG_ 2483351207 E2P_Cfg2_SW_Ver_Byte9 "ETH软件版本字节9";
CM_ SG_ 2483351207 E2P_Cfg2_SW_Ver_Byte10 "ETH软件版本字节10";
CM_ SG_ 2483351207 E2P_Cfg2_SW_Ver_Byte11 "ETH软件版本字节11";
CM_ SG_ 2483351207 E2P_Cfg2_SW_Ver_Byte12 "ETH软件版本字节12";
CM_ SG_ 2483351207 E2P_Cfg2_SW_Ver_Byte13 "ETH软件版本字节13";
CM_ SG_ 2483351207 E2P_Cfg2_SW_Ver_Byte14 "ETH软件版本字节14";
CM_ SG_ 2483351207 E2P_Cfg2_SW_Ver_Byte15 "ETH软件版本字节15";
CM_ SG_ 2483351207 E2P_Cfg2_SW_Ver_Byte16 "ETH软件版本字节16";
CM_ SG_ 2483351208 E2P_Cfg2_SW_Ver_Byte9 "ETH软件版本字节9";
CM_ SG_ 2483351208 E2P_Cfg2_SW_Ver_Byte10 "ETH软件版本字节10";
CM_ SG_ 2483351208 E2P_Cfg2_SW_Ver_Byte11 "ETH软件版本字节11";
CM_ SG_ 2483351208 E2P_Cfg2_SW_Ver_Byte12 "ETH软件版本字节12";
CM_ SG_ 2483351208 E2P_Cfg2_SW_Ver_Byte13 "ETH软件版本字节13";
CM_ SG_ 2483351208 E2P_Cfg2_SW_Ver_Byte14 "ETH软件版本字节14";
CM_ SG_ 2483351208 E2P_Cfg2_SW_Ver_Byte15 "ETH软件版本字节15";
CM_ SG_ 2483351208 E2P_Cfg2_SW_Ver_Byte16 "ETH软件版本字节16";
CM_ SG_ 2483351209 E2P_Cfg2_SW_Ver_Byte9 "ETH软件版本字节9";
CM_ SG_ 2483351209 E2P_Cfg2_SW_Ver_Byte10 "ETH软件版本字节10";
CM_ SG_ 2483351209 E2P_Cfg2_SW_Ver_Byte11 "ETH软件版本字节11";
CM_ SG_ 2483351209 E2P_Cfg2_SW_Ver_Byte12 "ETH软件版本字节12";
CM_ SG_ 2483351209 E2P_Cfg2_SW_Ver_Byte13 "ETH软件版本字节13";
CM_ SG_ 2483351209 E2P_Cfg2_SW_Ver_Byte14 "ETH软件版本字节14";
CM_ SG_ 2483351209 E2P_Cfg2_SW_Ver_Byte15 "ETH软件版本字节15";
CM_ SG_ 2483351209 E2P_Cfg2_SW_Ver_Byte16 "ETH软件版本字节16";
CM_ SG_ 2483351210 E2P_Cfg2_SW_Ver_Byte9 "ETH软件版本字节9";
CM_ SG_ 2483351210 E2P_Cfg2_SW_Ver_Byte10 "ETH软件版本字节10";
CM_ SG_ 2483351210 E2P_Cfg2_SW_Ver_Byte11 "ETH软件版本字节11";
CM_ SG_ 2483351210 E2P_Cfg2_SW_Ver_Byte12 "ETH软件版本字节12";
CM_ SG_ 2483351210 E2P_Cfg2_SW_Ver_Byte13 "ETH软件版本字节13";
CM_ SG_ 2483351210 E2P_Cfg2_SW_Ver_Byte14 "ETH软件版本字节14";
CM_ SG_ 2483351210 E2P_Cfg2_SW_Ver_Byte15 "ETH软件版本字节15";
CM_ SG_ 2483351210 E2P_Cfg2_SW_Ver_Byte16 "ETH软件版本字节16";
CM_ SG_ 2483351211 E2P_Cfg2_SW_Ver_Byte9 "ETH软件版本字节9";
CM_ SG_ 2483351211 E2P_Cfg2_SW_Ver_Byte10 "ETH软件版本字节10";
CM_ SG_ 2483351211 E2P_Cfg2_SW_Ver_Byte11 "ETH软件版本字节11";
CM_ SG_ 2483351211 E2P_Cfg2_SW_Ver_Byte12 "ETH软件版本字节12";
CM_ SG_ 2483351211 E2P_Cfg2_SW_Ver_Byte13 "ETH软件版本字节13";
CM_ SG_ 2483351211 E2P_Cfg2_SW_Ver_Byte14 "ETH软件版本字节14";
CM_ SG_ 2483351211 E2P_Cfg2_SW_Ver_Byte15 "ETH软件版本字节15";
CM_ SG_ 2483351211 E2P_Cfg2_SW_Ver_Byte16 "ETH软件版本字节16";
CM_ SG_ 2483351212 E2P_Cfg2_SW_Ver_Byte9 "ETH软件版本字节9";
CM_ SG_ 2483351212 E2P_Cfg2_SW_Ver_Byte10 "ETH软件版本字节10";
CM_ SG_ 2483351212 E2P_Cfg2_SW_Ver_Byte11 "ETH软件版本字节11";
CM_ SG_ 2483351212 E2P_Cfg2_SW_Ver_Byte12 "ETH软件版本字节12";
CM_ SG_ 2483351212 E2P_Cfg2_SW_Ver_Byte13 "ETH软件版本字节13";
CM_ SG_ 2483351212 E2P_Cfg2_SW_Ver_Byte14 "ETH软件版本字节14";
CM_ SG_ 2483351212 E2P_Cfg2_SW_Ver_Byte15 "ETH软件版本字节15";
CM_ SG_ 2483351212 E2P_Cfg2_SW_Ver_Byte16 "ETH软件版本字节16";
CM_ SG_ 2483351213 E2P_Cfg2_SW_Ver_Byte9 "ETH软件版本字节9";
CM_ SG_ 2483351213 E2P_Cfg2_SW_Ver_Byte10 "ETH软件版本字节10";
CM_ SG_ 2483351213 E2P_Cfg2_SW_Ver_Byte11 "ETH软件版本字节11";
CM_ SG_ 2483351213 E2P_Cfg2_SW_Ver_Byte12 "ETH软件版本字节12";
CM_ SG_ 2483351213 E2P_Cfg2_SW_Ver_Byte13 "ETH软件版本字节13";
CM_ SG_ 2483351213 E2P_Cfg2_SW_Ver_Byte14 "ETH软件版本字节14";
CM_ SG_ 2483351213 E2P_Cfg2_SW_Ver_Byte15 "ETH软件版本字节15";
CM_ SG_ 2483351213 E2P_Cfg2_SW_Ver_Byte16 "ETH软件版本字节16";
CM_ SG_ 2483351214 E2P_Cfg2_SW_Ver_Byte9 "ETH软件版本字节9";
CM_ SG_ 2483351214 E2P_Cfg2_SW_Ver_Byte10 "ETH软件版本字节10";
CM_ SG_ 2483351214 E2P_Cfg2_SW_Ver_Byte11 "ETH软件版本字节11";
CM_ SG_ 2483351214 E2P_Cfg2_SW_Ver_Byte12 "ETH软件版本字节12";
CM_ SG_ 2483351214 E2P_Cfg2_SW_Ver_Byte13 "ETH软件版本字节13";
CM_ SG_ 2483351214 E2P_Cfg2_SW_Ver_Byte14 "ETH软件版本字节14";
CM_ SG_ 2483351214 E2P_Cfg2_SW_Ver_Byte15 "ETH软件版本字节15";
CM_ SG_ 2483351214 E2P_Cfg2_SW_Ver_Byte16 "ETH软件版本字节16";
CM_ SG_ 2483351215 E2P_Cfg2_SW_Ver_Byte9 "ETH软件版本字节9";
CM_ SG_ 2483351215 E2P_Cfg2_SW_Ver_Byte10 "ETH软件版本字节10";
CM_ SG_ 2483351215 E2P_Cfg2_SW_Ver_Byte11 "ETH软件版本字节11";
CM_ SG_ 2483351215 E2P_Cfg2_SW_Ver_Byte12 "ETH软件版本字节12";
CM_ SG_ 2483351215 E2P_Cfg2_SW_Ver_Byte13 "ETH软件版本字节13";
CM_ SG_ 2483351215 E2P_Cfg2_SW_Ver_Byte14 "ETH软件版本字节14";
CM_ SG_ 2483351215 E2P_Cfg2_SW_Ver_Byte15 "ETH软件版本字节15";
CM_ SG_ 2483351215 E2P_Cfg2_SW_Ver_Byte16 "ETH软件版本字节16";
CM_ SG_ 2483416721 E2P_Cfg3_HW_Ver_Byte1 "ETH硬件版本字节1";
CM_ SG_ 2483416721 E2P_Cfg3_HW_Ver_Byte2 "ETH硬件版本字节2";
CM_ SG_ 2483416721 E2P_Cfg3_HW_Ver_Byte3 "ETH硬件版本字节3";
CM_ SG_ 2483416721 E2P_Cfg3_HW_Ver_Byte4 "ETH硬件版本字节4";
CM_ SG_ 2483416721 E2P_Cfg3_HW_Ver_Byte5 "ETH硬件版本字节5";
CM_ SG_ 2483416721 E2P_Cfg3_HW_Ver_Byte6 "ETH硬件版本字节6";
CM_ SG_ 2483416721 E2P_Cfg3_HW_Ver_Byte7 "ETH硬件版本字节7";
CM_ SG_ 2483416721 E2P_Cfg3_HW_Ver_Byte8 "ETH硬件版本字节8";
CM_ SG_ 2483416722 E2P_Cfg3_HW_Ver_Byte1 "ETH硬件版本字节1";
CM_ SG_ 2483416722 E2P_Cfg3_HW_Ver_Byte2 "ETH硬件版本字节2";
CM_ SG_ 2483416722 E2P_Cfg3_HW_Ver_Byte3 "ETH硬件版本字节3";
CM_ SG_ 2483416722 E2P_Cfg3_HW_Ver_Byte4 "ETH硬件版本字节4";
CM_ SG_ 2483416722 E2P_Cfg3_HW_Ver_Byte5 "ETH硬件版本字节5";
CM_ SG_ 2483416722 E2P_Cfg3_HW_Ver_Byte6 "ETH硬件版本字节6";
CM_ SG_ 2483416722 E2P_Cfg3_HW_Ver_Byte7 "ETH硬件版本字节7";
CM_ SG_ 2483416722 E2P_Cfg3_HW_Ver_Byte8 "ETH硬件版本字节8";
CM_ SG_ 2483416723 E2P_Cfg3_HW_Ver_Byte1 "ETH硬件版本字节1";
CM_ SG_ 2483416723 E2P_Cfg3_HW_Ver_Byte2 "ETH硬件版本字节2";
CM_ SG_ 2483416723 E2P_Cfg3_HW_Ver_Byte3 "ETH硬件版本字节3";
CM_ SG_ 2483416723 E2P_Cfg3_HW_Ver_Byte4 "ETH硬件版本字节4";
CM_ SG_ 2483416723 E2P_Cfg3_HW_Ver_Byte5 "ETH硬件版本字节5";
CM_ SG_ 2483416723 E2P_Cfg3_HW_Ver_Byte6 "ETH硬件版本字节6";
CM_ SG_ 2483416723 E2P_Cfg3_HW_Ver_Byte7 "ETH硬件版本字节7";
CM_ SG_ 2483416723 E2P_Cfg3_HW_Ver_Byte8 "ETH硬件版本字节8";
CM_ SG_ 2483416724 E2P_Cfg3_HW_Ver_Byte1 "ETH硬件版本字节1";
CM_ SG_ 2483416724 E2P_Cfg3_HW_Ver_Byte2 "ETH硬件版本字节2";
CM_ SG_ 2483416724 E2P_Cfg3_HW_Ver_Byte3 "ETH硬件版本字节3";
CM_ SG_ 2483416724 E2P_Cfg3_HW_Ver_Byte4 "ETH硬件版本字节4";
CM_ SG_ 2483416724 E2P_Cfg3_HW_Ver_Byte5 "ETH硬件版本字节5";
CM_ SG_ 2483416724 E2P_Cfg3_HW_Ver_Byte6 "ETH硬件版本字节6";
CM_ SG_ 2483416724 E2P_Cfg3_HW_Ver_Byte7 "ETH硬件版本字节7";
CM_ SG_ 2483416724 E2P_Cfg3_HW_Ver_Byte8 "ETH硬件版本字节8";
CM_ SG_ 2483416725 E2P_Cfg3_HW_Ver_Byte1 "ETH硬件版本字节1";
CM_ SG_ 2483416725 E2P_Cfg3_HW_Ver_Byte2 "ETH硬件版本字节2";
CM_ SG_ 2483416725 E2P_Cfg3_HW_Ver_Byte3 "ETH硬件版本字节3";
CM_ SG_ 2483416725 E2P_Cfg3_HW_Ver_Byte4 "ETH硬件版本字节4";
CM_ SG_ 2483416725 E2P_Cfg3_HW_Ver_Byte5 "ETH硬件版本字节5";
CM_ SG_ 2483416725 E2P_Cfg3_HW_Ver_Byte6 "ETH硬件版本字节6";
CM_ SG_ 2483416725 E2P_Cfg3_HW_Ver_Byte7 "ETH硬件版本字节7";
CM_ SG_ 2483416725 E2P_Cfg3_HW_Ver_Byte8 "ETH硬件版本字节8";
CM_ SG_ 2483416726 E2P_Cfg3_HW_Ver_Byte1 "ETH硬件版本字节1";
CM_ SG_ 2483416726 E2P_Cfg3_HW_Ver_Byte2 "ETH硬件版本字节2";
CM_ SG_ 2483416726 E2P_Cfg3_HW_Ver_Byte3 "ETH硬件版本字节3";
CM_ SG_ 2483416726 E2P_Cfg3_HW_Ver_Byte4 "ETH硬件版本字节4";
CM_ SG_ 2483416726 E2P_Cfg3_HW_Ver_Byte5 "ETH硬件版本字节5";
CM_ SG_ 2483416726 E2P_Cfg3_HW_Ver_Byte6 "ETH硬件版本字节6";
CM_ SG_ 2483416726 E2P_Cfg3_HW_Ver_Byte7 "ETH硬件版本字节7";
CM_ SG_ 2483416726 E2P_Cfg3_HW_Ver_Byte8 "ETH硬件版本字节8";
CM_ SG_ 2483416727 E2P_Cfg3_HW_Ver_Byte1 "ETH硬件版本字节1";
CM_ SG_ 2483416727 E2P_Cfg3_HW_Ver_Byte2 "ETH硬件版本字节2";
CM_ SG_ 2483416727 E2P_Cfg3_HW_Ver_Byte3 "ETH硬件版本字节3";
CM_ SG_ 2483416727 E2P_Cfg3_HW_Ver_Byte4 "ETH硬件版本字节4";
CM_ SG_ 2483416727 E2P_Cfg3_HW_Ver_Byte5 "ETH硬件版本字节5";
CM_ SG_ 2483416727 E2P_Cfg3_HW_Ver_Byte6 "ETH硬件版本字节6";
CM_ SG_ 2483416727 E2P_Cfg3_HW_Ver_Byte7 "ETH硬件版本字节7";
CM_ SG_ 2483416727 E2P_Cfg3_HW_Ver_Byte8 "ETH硬件版本字节8";
CM_ SG_ 2483416728 E2P_Cfg3_HW_Ver_Byte1 "ETH硬件版本字节1";
CM_ SG_ 2483416728 E2P_Cfg3_HW_Ver_Byte2 "ETH硬件版本字节2";
CM_ SG_ 2483416728 E2P_Cfg3_HW_Ver_Byte3 "ETH硬件版本字节3";
CM_ SG_ 2483416728 E2P_Cfg3_HW_Ver_Byte4 "ETH硬件版本字节4";
CM_ SG_ 2483416728 E2P_Cfg3_HW_Ver_Byte5 "ETH硬件版本字节5";
CM_ SG_ 2483416728 E2P_Cfg3_HW_Ver_Byte6 "ETH硬件版本字节6";
CM_ SG_ 2483416728 E2P_Cfg3_HW_Ver_Byte7 "ETH硬件版本字节7";
CM_ SG_ 2483416728 E2P_Cfg3_HW_Ver_Byte8 "ETH硬件版本字节8";
CM_ SG_ 2483416729 E2P_Cfg3_HW_Ver_Byte1 "ETH硬件版本字节1";
CM_ SG_ 2483416729 E2P_Cfg3_HW_Ver_Byte2 "ETH硬件版本字节2";
CM_ SG_ 2483416729 E2P_Cfg3_HW_Ver_Byte3 "ETH硬件版本字节3";
CM_ SG_ 2483416729 E2P_Cfg3_HW_Ver_Byte4 "ETH硬件版本字节4";
CM_ SG_ 2483416729 E2P_Cfg3_HW_Ver_Byte5 "ETH硬件版本字节5";
CM_ SG_ 2483416729 E2P_Cfg3_HW_Ver_Byte6 "ETH硬件版本字节6";
CM_ SG_ 2483416729 E2P_Cfg3_HW_Ver_Byte7 "ETH硬件版本字节7";
CM_ SG_ 2483416729 E2P_Cfg3_HW_Ver_Byte8 "ETH硬件版本字节8";
CM_ SG_ 2483416730 E2P_Cfg3_HW_Ver_Byte1 "ETH硬件版本字节1";
CM_ SG_ 2483416730 E2P_Cfg3_HW_Ver_Byte2 "ETH硬件版本字节2";
CM_ SG_ 2483416730 E2P_Cfg3_HW_Ver_Byte3 "ETH硬件版本字节3";
CM_ SG_ 2483416730 E2P_Cfg3_HW_Ver_Byte4 "ETH硬件版本字节4";
CM_ SG_ 2483416730 E2P_Cfg3_HW_Ver_Byte5 "ETH硬件版本字节5";
CM_ SG_ 2483416730 E2P_Cfg3_HW_Ver_Byte6 "ETH硬件版本字节6";
CM_ SG_ 2483416730 E2P_Cfg3_HW_Ver_Byte7 "ETH硬件版本字节7";
CM_ SG_ 2483416730 E2P_Cfg3_HW_Ver_Byte8 "ETH硬件版本字节8";
CM_ SG_ 2483416731 E2P_Cfg3_HW_Ver_Byte1 "ETH硬件版本字节1";
CM_ SG_ 2483416731 E2P_Cfg3_HW_Ver_Byte2 "ETH硬件版本字节2";
CM_ SG_ 2483416731 E2P_Cfg3_HW_Ver_Byte3 "ETH硬件版本字节3";
CM_ SG_ 2483416731 E2P_Cfg3_HW_Ver_Byte4 "ETH硬件版本字节4";
CM_ SG_ 2483416731 E2P_Cfg3_HW_Ver_Byte5 "ETH硬件版本字节5";
CM_ SG_ 2483416731 E2P_Cfg3_HW_Ver_Byte6 "ETH硬件版本字节6";
CM_ SG_ 2483416731 E2P_Cfg3_HW_Ver_Byte7 "ETH硬件版本字节7";
CM_ SG_ 2483416731 E2P_Cfg3_HW_Ver_Byte8 "ETH硬件版本字节8";
CM_ SG_ 2483416732 E2P_Cfg3_HW_Ver_Byte1 "ETH硬件版本字节1";
CM_ SG_ 2483416732 E2P_Cfg3_HW_Ver_Byte2 "ETH硬件版本字节2";
CM_ SG_ 2483416732 E2P_Cfg3_HW_Ver_Byte3 "ETH硬件版本字节3";
CM_ SG_ 2483416732 E2P_Cfg3_HW_Ver_Byte4 "ETH硬件版本字节4";
CM_ SG_ 2483416732 E2P_Cfg3_HW_Ver_Byte5 "ETH硬件版本字节5";
CM_ SG_ 2483416732 E2P_Cfg3_HW_Ver_Byte6 "ETH硬件版本字节6";
CM_ SG_ 2483416732 E2P_Cfg3_HW_Ver_Byte7 "ETH硬件版本字节7";
CM_ SG_ 2483416732 E2P_Cfg3_HW_Ver_Byte8 "ETH硬件版本字节8";
CM_ SG_ 2483416733 E2P_Cfg3_HW_Ver_Byte1 "ETH硬件版本字节1";
CM_ SG_ 2483416733 E2P_Cfg3_HW_Ver_Byte2 "ETH硬件版本字节2";
CM_ SG_ 2483416733 E2P_Cfg3_HW_Ver_Byte3 "ETH硬件版本字节3";
CM_ SG_ 2483416733 E2P_Cfg3_HW_Ver_Byte4 "ETH硬件版本字节4";
CM_ SG_ 2483416733 E2P_Cfg3_HW_Ver_Byte5 "ETH硬件版本字节5";
CM_ SG_ 2483416733 E2P_Cfg3_HW_Ver_Byte6 "ETH硬件版本字节6";
CM_ SG_ 2483416733 E2P_Cfg3_HW_Ver_Byte7 "ETH硬件版本字节7";
CM_ SG_ 2483416733 E2P_Cfg3_HW_Ver_Byte8 "ETH硬件版本字节8";
CM_ SG_ 2483416734 E2P_Cfg3_HW_Ver_Byte1 "ETH硬件版本字节1";
CM_ SG_ 2483416734 E2P_Cfg3_HW_Ver_Byte2 "ETH硬件版本字节2";
CM_ SG_ 2483416734 E2P_Cfg3_HW_Ver_Byte3 "ETH硬件版本字节3";
CM_ SG_ 2483416734 E2P_Cfg3_HW_Ver_Byte4 "ETH硬件版本字节4";
CM_ SG_ 2483416734 E2P_Cfg3_HW_Ver_Byte5 "ETH硬件版本字节5";
CM_ SG_ 2483416734 E2P_Cfg3_HW_Ver_Byte6 "ETH硬件版本字节6";
CM_ SG_ 2483416734 E2P_Cfg3_HW_Ver_Byte7 "ETH硬件版本字节7";
CM_ SG_ 2483416734 E2P_Cfg3_HW_Ver_Byte8 "ETH硬件版本字节8";
CM_ SG_ 2483416735 E2P_Cfg3_HW_Ver_Byte1 "ETH硬件版本字节1";
CM_ SG_ 2483416735 E2P_Cfg3_HW_Ver_Byte2 "ETH硬件版本字节2";
CM_ SG_ 2483416735 E2P_Cfg3_HW_Ver_Byte3 "ETH硬件版本字节3";
CM_ SG_ 2483416735 E2P_Cfg3_HW_Ver_Byte4 "ETH硬件版本字节4";
CM_ SG_ 2483416735 E2P_Cfg3_HW_Ver_Byte5 "ETH硬件版本字节5";
CM_ SG_ 2483416735 E2P_Cfg3_HW_Ver_Byte6 "ETH硬件版本字节6";
CM_ SG_ 2483416735 E2P_Cfg3_HW_Ver_Byte7 "ETH硬件版本字节7";
CM_ SG_ 2483416735 E2P_Cfg3_HW_Ver_Byte8 "ETH硬件版本字节8";
CM_ SG_ 2483416736 E2P_Cfg3_HW_Ver_Byte1 "ETH硬件版本字节1";
CM_ SG_ 2483416736 E2P_Cfg3_HW_Ver_Byte2 "ETH硬件版本字节2";
CM_ SG_ 2483416736 E2P_Cfg3_HW_Ver_Byte3 "ETH硬件版本字节3";
CM_ SG_ 2483416736 E2P_Cfg3_HW_Ver_Byte4 "ETH硬件版本字节4";
CM_ SG_ 2483416736 E2P_Cfg3_HW_Ver_Byte5 "ETH硬件版本字节5";
CM_ SG_ 2483416736 E2P_Cfg3_HW_Ver_Byte6 "ETH硬件版本字节6";
CM_ SG_ 2483416736 E2P_Cfg3_HW_Ver_Byte7 "ETH硬件版本字节7";
CM_ SG_ 2483416736 E2P_Cfg3_HW_Ver_Byte8 "ETH硬件版本字节8";
CM_ SG_ 2483416737 E2P_Cfg3_HW_Ver_Byte1 "ETH硬件版本字节1";
CM_ SG_ 2483416737 E2P_Cfg3_HW_Ver_Byte2 "ETH硬件版本字节2";
CM_ SG_ 2483416737 E2P_Cfg3_HW_Ver_Byte3 "ETH硬件版本字节3";
CM_ SG_ 2483416737 E2P_Cfg3_HW_Ver_Byte4 "ETH硬件版本字节4";
CM_ SG_ 2483416737 E2P_Cfg3_HW_Ver_Byte5 "ETH硬件版本字节5";
CM_ SG_ 2483416737 E2P_Cfg3_HW_Ver_Byte6 "ETH硬件版本字节6";
CM_ SG_ 2483416737 E2P_Cfg3_HW_Ver_Byte7 "ETH硬件版本字节7";
CM_ SG_ 2483416737 E2P_Cfg3_HW_Ver_Byte8 "ETH硬件版本字节8";
CM_ SG_ 2483416738 E2P_Cfg3_HW_Ver_Byte1 "ETH硬件版本字节1";
CM_ SG_ 2483416738 E2P_Cfg3_HW_Ver_Byte2 "ETH硬件版本字节2";
CM_ SG_ 2483416738 E2P_Cfg3_HW_Ver_Byte3 "ETH硬件版本字节3";
CM_ SG_ 2483416738 E2P_Cfg3_HW_Ver_Byte4 "ETH硬件版本字节4";
CM_ SG_ 2483416738 E2P_Cfg3_HW_Ver_Byte5 "ETH硬件版本字节5";
CM_ SG_ 2483416738 E2P_Cfg3_HW_Ver_Byte6 "ETH硬件版本字节6";
CM_ SG_ 2483416738 E2P_Cfg3_HW_Ver_Byte7 "ETH硬件版本字节7";
CM_ SG_ 2483416738 E2P_Cfg3_HW_Ver_Byte8 "ETH硬件版本字节8";
CM_ SG_ 2483416739 E2P_Cfg3_HW_Ver_Byte1 "ETH硬件版本字节1";
CM_ SG_ 2483416739 E2P_Cfg3_HW_Ver_Byte2 "ETH硬件版本字节2";
CM_ SG_ 2483416739 E2P_Cfg3_HW_Ver_Byte3 "ETH硬件版本字节3";
CM_ SG_ 2483416739 E2P_Cfg3_HW_Ver_Byte4 "ETH硬件版本字节4";
CM_ SG_ 2483416739 E2P_Cfg3_HW_Ver_Byte5 "ETH硬件版本字节5";
CM_ SG_ 2483416739 E2P_Cfg3_HW_Ver_Byte6 "ETH硬件版本字节6";
CM_ SG_ 2483416739 E2P_Cfg3_HW_Ver_Byte7 "ETH硬件版本字节7";
CM_ SG_ 2483416739 E2P_Cfg3_HW_Ver_Byte8 "ETH硬件版本字节8";
CM_ SG_ 2483416740 E2P_Cfg3_HW_Ver_Byte1 "ETH硬件版本字节1";
CM_ SG_ 2483416740 E2P_Cfg3_HW_Ver_Byte2 "ETH硬件版本字节2";
CM_ SG_ 2483416740 E2P_Cfg3_HW_Ver_Byte3 "ETH硬件版本字节3";
CM_ SG_ 2483416740 E2P_Cfg3_HW_Ver_Byte4 "ETH硬件版本字节4";
CM_ SG_ 2483416740 E2P_Cfg3_HW_Ver_Byte5 "ETH硬件版本字节5";
CM_ SG_ 2483416740 E2P_Cfg3_HW_Ver_Byte6 "ETH硬件版本字节6";
CM_ SG_ 2483416740 E2P_Cfg3_HW_Ver_Byte7 "ETH硬件版本字节7";
CM_ SG_ 2483416740 E2P_Cfg3_HW_Ver_Byte8 "ETH硬件版本字节8";
CM_ SG_ 2483416741 E2P_Cfg3_HW_Ver_Byte1 "ETH硬件版本字节1";
CM_ SG_ 2483416741 E2P_Cfg3_HW_Ver_Byte2 "ETH硬件版本字节2";
CM_ SG_ 2483416741 E2P_Cfg3_HW_Ver_Byte3 "ETH硬件版本字节3";
CM_ SG_ 2483416741 E2P_Cfg3_HW_Ver_Byte4 "ETH硬件版本字节4";
CM_ SG_ 2483416741 E2P_Cfg3_HW_Ver_Byte5 "ETH硬件版本字节5";
CM_ SG_ 2483416741 E2P_Cfg3_HW_Ver_Byte6 "ETH硬件版本字节6";
CM_ SG_ 2483416741 E2P_Cfg3_HW_Ver_Byte7 "ETH硬件版本字节7";
CM_ SG_ 2483416741 E2P_Cfg3_HW_Ver_Byte8 "ETH硬件版本字节8";
CM_ SG_ 2483416742 E2P_Cfg3_HW_Ver_Byte1 "ETH硬件版本字节1";
CM_ SG_ 2483416742 E2P_Cfg3_HW_Ver_Byte2 "ETH硬件版本字节2";
CM_ SG_ 2483416742 E2P_Cfg3_HW_Ver_Byte3 "ETH硬件版本字节3";
CM_ SG_ 2483416742 E2P_Cfg3_HW_Ver_Byte4 "ETH硬件版本字节4";
CM_ SG_ 2483416742 E2P_Cfg3_HW_Ver_Byte5 "ETH硬件版本字节5";
CM_ SG_ 2483416742 E2P_Cfg3_HW_Ver_Byte6 "ETH硬件版本字节6";
CM_ SG_ 2483416742 E2P_Cfg3_HW_Ver_Byte7 "ETH硬件版本字节7";
CM_ SG_ 2483416742 E2P_Cfg3_HW_Ver_Byte8 "ETH硬件版本字节8";
VERSION ""

NS_ :

BS_:

BU_: MBMU PC SBMU IMM ETH DCDC LEMS

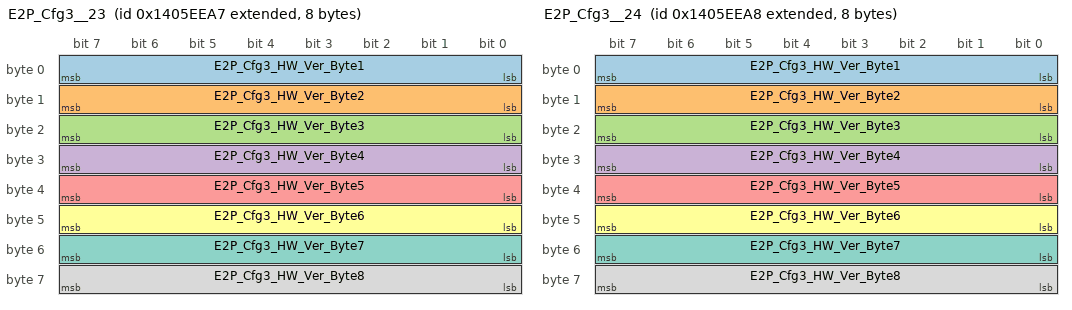
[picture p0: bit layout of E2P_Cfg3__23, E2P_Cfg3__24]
BO_ 2483416743 E2P_Cfg3__23: 8 ETH
 SG_ E2P_Cfg3_HW_Ver_Byte1 : 0|8@1+ (1,0) [0|255] ""  PC
 SG_ E2P_Cfg3_HW_Ver_Byte2 : 8|8@1+ (1,0) [0|255] ""  PC
 SG_ E2P_Cfg3_HW_Ver_Byte3 : 16|8@1+ (1,0) [0|255] ""  PC
 SG_ E2P_Cfg3_HW_Ver_Byte4 : 24|8@1+ (1,0) [0|255] ""  PC
 SG_ E2P_Cfg3_HW_Ver_Byte5 : 32|8@1+ (1,0) [0|255] ""  PC
 SG_ E2P_Cfg3_HW_Ver_Byte6 : 40|8@1+ (1,0) [0|255] ""  PC
 SG_ E2P_Cfg3_HW_Ver_Byte7 : 48|8@1+ (1,0) [0|255] ""  PC
 SG_ E2P_Cfg3_HW_Ver_Byte8 : 56|8@1+ (1,0) [0|255] ""  PC

BO_ 2483416744 E2P_Cfg3__24: 8 ETH
 SG_ E2P_Cfg3_HW_Ver_Byte1 : 0|8@1+ (1,0) [0|255] ""  PC
 SG_ E2P_Cfg3_HW_Ver_Byte2 : 8|8@1+ (1,0) [0|255] ""  PC
 SG_ E2P_Cfg3_HW_Ver_Byte3 : 16|8@1+ (1,0) [0|255] ""  PC
 SG_ E2P_Cfg3_HW_Ver_Byte4 : 24|8@1+ (1,0) [0|255] ""  PC
 SG_ E2P_Cfg3_HW_Ver_Byte5 : 32|8@1+ (1,0) [0|255] ""  PC
 SG_ E2P_Cfg3_HW_Ver_Byte6 : 40|8@1+ (1,0) [0|255] ""  PC
 SG_ E2P_Cfg3_HW_Ver_Byte7 : 48|8@1+ (1,0) [0|255] ""  PC
 SG_ E2P_Cfg3_HW_Ver_Byte8 : 56|8@1+ (1,0) [0|255] ""  PC

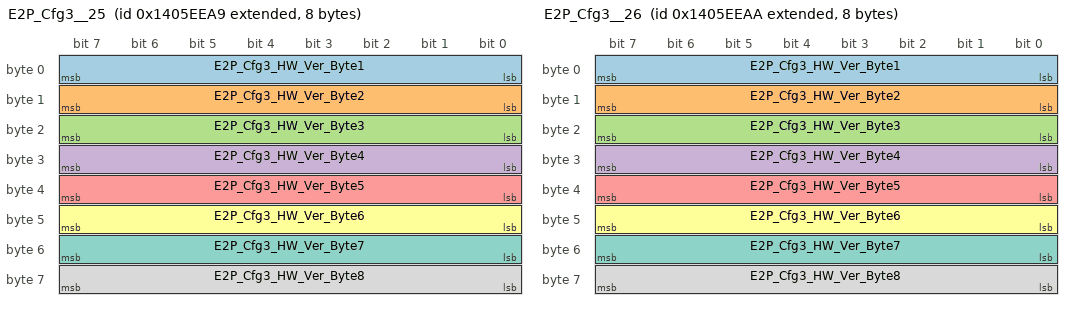
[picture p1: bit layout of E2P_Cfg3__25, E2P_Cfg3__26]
BO_ 2483416745 E2P_Cfg3__25: 8 ETH
 SG_ E2P_Cfg3_HW_Ver_Byte1 : 0|8@1+ (1,0) [0|255] ""  PC
 SG_ E2P_Cfg3_HW_Ver_Byte2 : 8|8@1+ (1,0) [0|255] ""  PC
 SG_ E2P_Cfg3_HW_Ver_Byte3 : 16|8@1+ (1,0) [0|255] ""  PC
 SG_ E2P_Cfg3_HW_Ver_Byte4 : 24|8@1+ (1,0) [0|255] ""  PC
 SG_ E2P_Cfg3_HW_Ver_Byte5 : 32|8@1+ (1,0) [0|255] ""  PC
 SG_ E2P_Cfg3_HW_Ver_Byte6 : 40|8@1+ (1,0) [0|255] ""  PC
 SG_ E2P_Cfg3_HW_Ver_Byte7 : 48|8@1+ (1,0) [0|255] ""  PC
 SG_ E2P_Cfg3_HW_Ver_Byte8 : 56|8@1+ (1,0) [0|255] ""  PC

BO_ 2483416746 E2P_Cfg3__26: 8 ETH
 SG_ E2P_Cfg3_HW_Ver_Byte1 : 0|8@1+ (1,0) [0|255] ""  PC
 SG_ E2P_Cfg3_HW_Ver_Byte2 : 8|8@1+ (1,0) [0|255] ""  PC
 SG_ E2P_Cfg3_HW_Ver_Byte3 : 16|8@1+ (1,0) [0|255] ""  PC
 SG_ E2P_Cfg3_HW_Ver_Byte4 : 24|8@1+ (1,0) [0|255] ""  PC
 SG_ E2P_Cfg3_HW_Ver_Byte5 : 32|8@1+ (1,0) [0|255] ""  PC
 SG_ E2P_Cfg3_HW_Ver_Byte6 : 40|8@1+ (1,0) [0|255] ""  PC
 SG_ E2P_Cfg3_HW_Ver_Byte7 : 48|8@1+ (1,0) [0|255] ""  PC
 SG_ E2P_Cfg3_HW_Ver_Byte8 : 56|8@1+ (1,0) [0|255] ""  PC

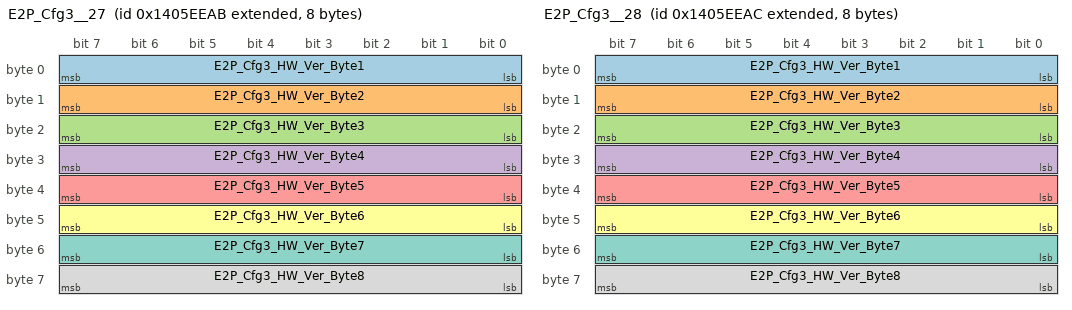
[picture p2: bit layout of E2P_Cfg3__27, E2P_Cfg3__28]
BO_ 2483416747 E2P_Cfg3__27: 8 ETH
 SG_ E2P_Cfg3_HW_Ver_Byte1 : 0|8@1+ (1,0) [0|255] ""  PC
 SG_ E2P_Cfg3_HW_Ver_Byte2 : 8|8@1+ (1,0) [0|255] ""  PC
 SG_ E2P_Cfg3_HW_Ver_Byte3 : 16|8@1+ (1,0) [0|255] ""  PC
 SG_ E2P_Cfg3_HW_Ver_Byte4 : 24|8@1+ (1,0) [0|255] ""  PC
 SG_ E2P_Cfg3_HW_Ver_Byte5 : 32|8@1+ (1,0) [0|255] ""  PC
 SG_ E2P_Cfg3_HW_Ver_Byte6 : 40|8@1+ (1,0) [0|255] ""  PC
 SG_ E2P_Cfg3_HW_Ver_Byte7 : 48|8@1+ (1,0) [0|255] ""  PC
 SG_ E2P_Cfg3_HW_Ver_Byte8 : 56|8@1+ (1,0) [0|255] ""  PC

BO_ 2483416748 E2P_Cfg3__28: 8 ETH
 SG_ E2P_Cfg3_HW_Ver_Byte1 : 0|8@1+ (1,0) [0|255] ""  PC
 SG_ E2P_Cfg3_HW_Ver_Byte2 : 8|8@1+ (1,0) [0|255] ""  PC
 SG_ E2P_Cfg3_HW_Ver_Byte3 : 16|8@1+ (1,0) [0|255] ""  PC
 SG_ E2P_Cfg3_HW_Ver_Byte4 : 24|8@1+ (1,0) [0|255] ""  PC
 SG_ E2P_Cfg3_HW_Ver_Byte5 : 32|8@1+ (1,0) [0|255] ""  PC
 SG_ E2P_Cfg3_HW_Ver_Byte6 : 40|8@1+ (1,0) [0|255] ""  PC
 SG_ E2P_Cfg3_HW_Ver_Byte7 : 48|8@1+ (1,0) [0|255] ""  PC
 SG_ E2P_Cfg3_HW_Ver_Byte8 : 56|8@1+ (1,0) [0|255] ""  PC

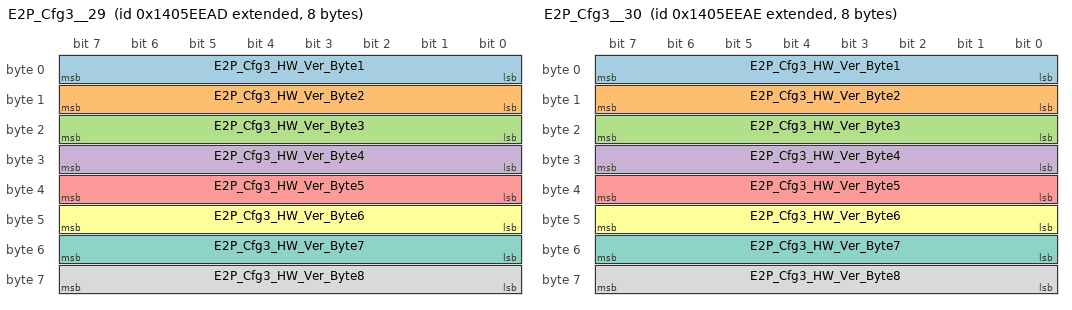
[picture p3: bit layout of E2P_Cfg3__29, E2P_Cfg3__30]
BO_ 2483416749 E2P_Cfg3__29: 8 ETH
 SG_ E2P_Cfg3_HW_Ver_Byte1 : 0|8@1+ (1,0) [0|255] ""  PC
 SG_ E2P_Cfg3_HW_Ver_Byte2 : 8|8@1+ (1,0) [0|255] ""  PC
 SG_ E2P_Cfg3_HW_Ver_Byte3 : 16|8@1+ (1,0) [0|255] ""  PC
 SG_ E2P_Cfg3_HW_Ver_Byte4 : 24|8@1+ (1,0) [0|255] ""  PC
 SG_ E2P_Cfg3_HW_Ver_Byte5 : 32|8@1+ (1,0) [0|255] ""  PC
 SG_ E2P_Cfg3_HW_Ver_Byte6 : 40|8@1+ (1,0) [0|255] ""  PC
 SG_ E2P_Cfg3_HW_Ver_Byte7 : 48|8@1+ (1,0) [0|255] ""  PC
 SG_ E2P_Cfg3_HW_Ver_Byte8 : 56|8@1+ (1,0) [0|255] ""  PC

BO_ 2483416750 E2P_Cfg3__30: 8 ETH
 SG_ E2P_Cfg3_HW_Ver_Byte1 : 0|8@1+ (1,0) [0|255] ""  PC
 SG_ E2P_Cfg3_HW_Ver_Byte2 : 8|8@1+ (1,0) [0|255] ""  PC
 SG_ E2P_Cfg3_HW_Ver_Byte3 : 16|8@1+ (1,0) [0|255] ""  PC
 SG_ E2P_Cfg3_HW_Ver_Byte4 : 24|8@1+ (1,0) [0|255] ""  PC
 SG_ E2P_Cfg3_HW_Ver_Byte5 : 32|8@1+ (1,0) [0|255] ""  PC
 SG_ E2P_Cfg3_HW_Ver_Byte6 : 40|8@1+ (1,0) [0|255] ""  PC
 SG_ E2P_Cfg3_HW_Ver_Byte7 : 48|8@1+ (1,0) [0|255] ""  PC
 SG_ E2P_Cfg3_HW_Ver_Byte8 : 56|8@1+ (1,0) [0|255] ""  PC

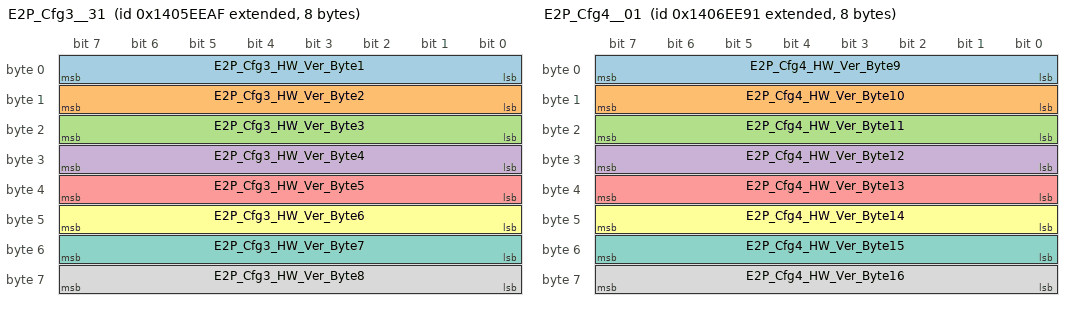
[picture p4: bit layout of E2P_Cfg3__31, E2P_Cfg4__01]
BO_ 2483416751 E2P_Cfg3__31: 8 ETH
 SG_ E2P_Cfg3_HW_Ver_Byte1 : 0|8@1+ (1,0) [0|255] ""  PC
 SG_ E2P_Cfg3_HW_Ver_Byte2 : 8|8@1+ (1,0) [0|255] ""  PC
 SG_ E2P_Cfg3_HW_Ver_Byte3 : 16|8@1+ (1,0) [0|255] ""  PC
 SG_ E2P_Cfg3_HW_Ver_Byte4 : 24|8@1+ (1,0) [0|255] ""  PC
 SG_ E2P_Cfg3_HW_Ver_Byte5 : 32|8@1+ (1,0) [0|255] ""  PC
 SG_ E2P_Cfg3_HW_Ver_Byte6 : 40|8@1+ (1,0) [0|255] ""  PC
 SG_ E2P_Cfg3_HW_Ver_Byte7 : 48|8@1+ (1,0) [0|255] ""  PC
 SG_ E2P_Cfg3_HW_Ver_Byte8 : 56|8@1+ (1,0) [0|255] ""  PC

BO_ 2483482257 E2P_Cfg4__01: 8 ETH
 SG_ E2P_Cfg4_HW_Ver_Byte9 : 0|8@1+ (1,0) [0|255] ""  PC
 SG_ E2P_Cfg4_HW_Ver_Byte10 : 8|8@1+ (1,0) [0|255] ""  PC
 SG_ E2P_Cfg4_HW_Ver_Byte11 : 16|8@1+ (1,0) [0|255] ""  PC
 SG_ E2P_Cfg4_HW_Ver_Byte12 : 24|8@1+ (1,0) [0|255] ""  PC
 SG_ E2P_Cfg4_HW_Ver_Byte13 : 32|8@1+ (1,0) [0|255] ""  PC
 SG_ E2P_Cfg4_HW_Ver_Byte14 : 40|8@1+ (1,0) [0|255] ""  PC
 SG_ E2P_Cfg4_HW_Ver_Byte15 : 48|8@1+ (1,0) [0|255] ""  PC
 SG_ E2P_Cfg4_HW_Ver_Byte16 : 56|8@1+ (1,0) [0|255] ""  PC

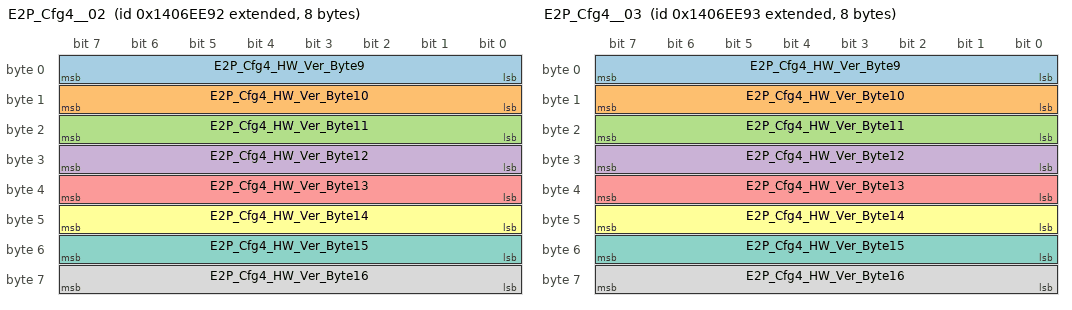
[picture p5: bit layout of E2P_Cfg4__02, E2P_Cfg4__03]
BO_ 2483482258 E2P_Cfg4__02: 8 ETH
 SG_ E2P_Cfg4_HW_Ver_Byte9 : 0|8@1+ (1,0) [0|255] ""  PC
 SG_ E2P_Cfg4_HW_Ver_Byte10 : 8|8@1+ (1,0) [0|255] ""  PC
 SG_ E2P_Cfg4_HW_Ver_Byte11 : 16|8@1+ (1,0) [0|255] ""  PC
 SG_ E2P_Cfg4_HW_Ver_Byte12 : 24|8@1+ (1,0) [0|255] ""  PC
 SG_ E2P_Cfg4_HW_Ver_Byte13 : 32|8@1+ (1,0) [0|255] ""  PC
 SG_ E2P_Cfg4_HW_Ver_Byte14 : 40|8@1+ (1,0) [0|255] ""  PC
 SG_ E2P_Cfg4_HW_Ver_Byte15 : 48|8@1+ (1,0) [0|255] ""  PC
 SG_ E2P_Cfg4_HW_Ver_Byte16 : 56|8@1+ (1,0) [0|255] ""  PC

BO_ 2483482259 E2P_Cfg4__03: 8 ETH
 SG_ E2P_Cfg4_HW_Ver_Byte9 : 0|8@1+ (1,0) [0|255] ""  PC
 SG_ E2P_Cfg4_HW_Ver_Byte10 : 8|8@1+ (1,0) [0|255] ""  PC
 SG_ E2P_Cfg4_HW_Ver_Byte11 : 16|8@1+ (1,0) [0|255] ""  PC
 SG_ E2P_Cfg4_HW_Ver_Byte12 : 24|8@1+ (1,0) [0|255] ""  PC
 SG_ E2P_Cfg4_HW_Ver_Byte13 : 32|8@1+ (1,0) [0|255] ""  PC
 SG_ E2P_Cfg4_HW_Ver_Byte14 : 40|8@1+ (1,0) [0|255] ""  PC
 SG_ E2P_Cfg4_HW_Ver_Byte15 : 48|8@1+ (1,0) [0|255] ""  PC
 SG_ E2P_Cfg4_HW_Ver_Byte16 : 56|8@1+ (1,0) [0|255] ""  PC

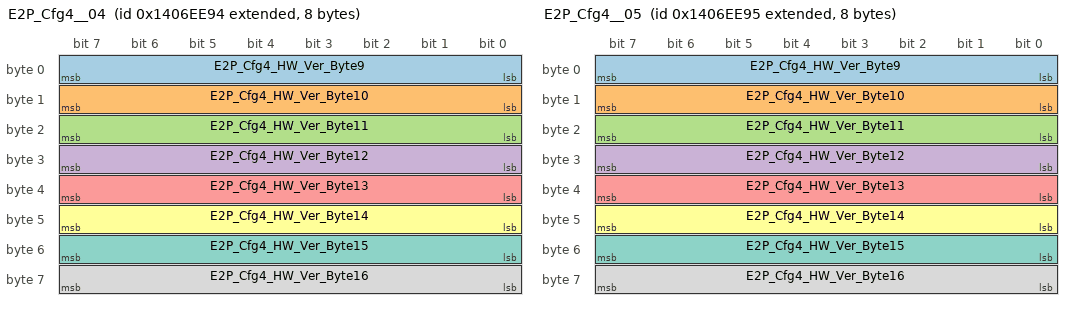
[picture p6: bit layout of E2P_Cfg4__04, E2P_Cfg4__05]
BO_ 2483482260 E2P_Cfg4__04: 8 ETH
 SG_ E2P_Cfg4_HW_Ver_Byte9 : 0|8@1+ (1,0) [0|255] ""  PC
 SG_ E2P_Cfg4_HW_Ver_Byte10 : 8|8@1+ (1,0) [0|255] ""  PC
 SG_ E2P_Cfg4_HW_Ver_Byte11 : 16|8@1+ (1,0) [0|255] ""  PC
 SG_ E2P_Cfg4_HW_Ver_Byte12 : 24|8@1+ (1,0) [0|255] ""  PC
 SG_ E2P_Cfg4_HW_Ver_Byte13 : 32|8@1+ (1,0) [0|255] ""  PC
 SG_ E2P_Cfg4_HW_Ver_Byte14 : 40|8@1+ (1,0) [0|255] ""  PC
 SG_ E2P_Cfg4_HW_Ver_Byte15 : 48|8@1+ (1,0) [0|255] ""  PC
 SG_ E2P_Cfg4_HW_Ver_Byte16 : 56|8@1+ (1,0) [0|255] ""  PC

BO_ 2483482261 E2P_Cfg4__05: 8 ETH
 SG_ E2P_Cfg4_HW_Ver_Byte9 : 0|8@1+ (1,0) [0|255] ""  PC
 SG_ E2P_Cfg4_HW_Ver_Byte10 : 8|8@1+ (1,0) [0|255] ""  PC
 SG_ E2P_Cfg4_HW_Ver_Byte11 : 16|8@1+ (1,0) [0|255] ""  PC
 SG_ E2P_Cfg4_HW_Ver_Byte12 : 24|8@1+ (1,0) [0|255] ""  PC
 SG_ E2P_Cfg4_HW_Ver_Byte13 : 32|8@1+ (1,0) [0|255] ""  PC
 SG_ E2P_Cfg4_HW_Ver_Byte14 : 40|8@1+ (1,0) [0|255] ""  PC
 SG_ E2P_Cfg4_HW_Ver_Byte15 : 48|8@1+ (1,0) [0|255] ""  PC
 SG_ E2P_Cfg4_HW_Ver_Byte16 : 56|8@1+ (1,0) [0|255] ""  PC

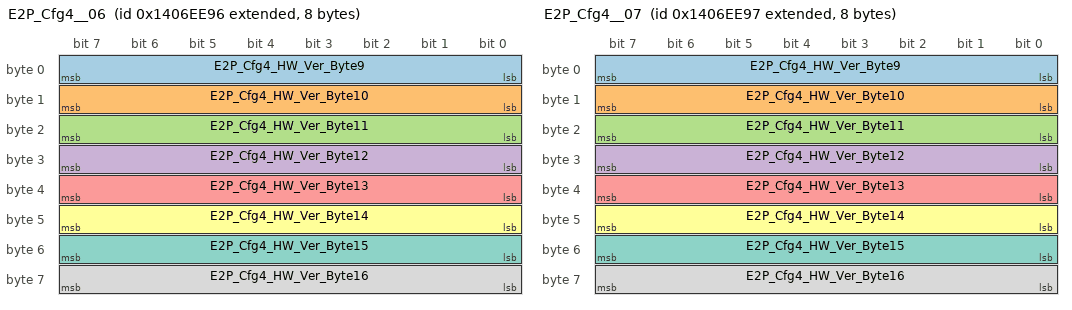
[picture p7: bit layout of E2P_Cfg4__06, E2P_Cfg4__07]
BO_ 2483482262 E2P_Cfg4__06: 8 ETH
 SG_ E2P_Cfg4_HW_Ver_Byte9 : 0|8@1+ (1,0) [0|255] ""  PC
 SG_ E2P_Cfg4_HW_Ver_Byte10 : 8|8@1+ (1,0) [0|255] ""  PC
 SG_ E2P_Cfg4_HW_Ver_Byte11 : 16|8@1+ (1,0) [0|255] ""  PC
 SG_ E2P_Cfg4_HW_Ver_Byte12 : 24|8@1+ (1,0) [0|255] ""  PC
 SG_ E2P_Cfg4_HW_Ver_Byte13 : 32|8@1+ (1,0) [0|255] ""  PC
 SG_ E2P_Cfg4_HW_Ver_Byte14 : 40|8@1+ (1,0) [0|255] ""  PC
 SG_ E2P_Cfg4_HW_Ver_Byte15 : 48|8@1+ (1,0) [0|255] ""  PC
 SG_ E2P_Cfg4_HW_Ver_Byte16 : 56|8@1+ (1,0) [0|255] ""  PC

BO_ 2483482263 E2P_Cfg4__07: 8 ETH
 SG_ E2P_Cfg4_HW_Ver_Byte9 : 0|8@1+ (1,0) [0|255] ""  PC
 SG_ E2P_Cfg4_HW_Ver_Byte10 : 8|8@1+ (1,0) [0|255] ""  PC
 SG_ E2P_Cfg4_HW_Ver_Byte11 : 16|8@1+ (1,0) [0|255] ""  PC
 SG_ E2P_Cfg4_HW_Ver_Byte12 : 24|8@1+ (1,0) [0|255] ""  PC
 SG_ E2P_Cfg4_HW_Ver_Byte13 : 32|8@1+ (1,0) [0|255] ""  PC
 SG_ E2P_Cfg4_HW_Ver_Byte14 : 40|8@1+ (1,0) [0|255] ""  PC
 SG_ E2P_Cfg4_HW_Ver_Byte15 : 48|8@1+ (1,0) [0|255] ""  PC
 SG_ E2P_Cfg4_HW_Ver_Byte16 : 56|8@1+ (1,0) [0|255] ""  PC

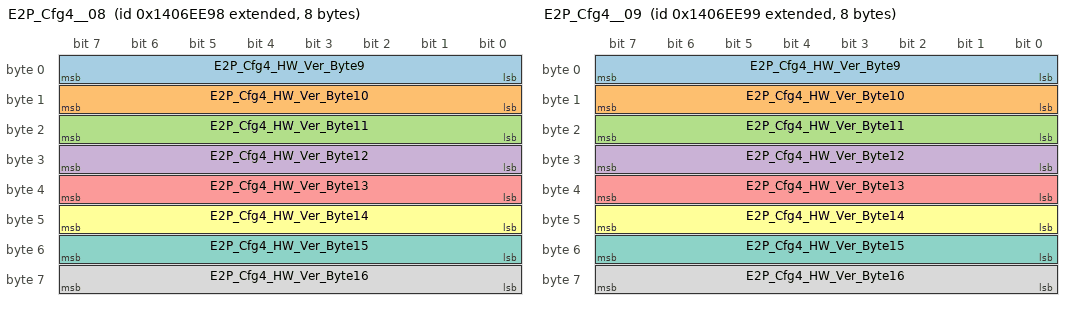
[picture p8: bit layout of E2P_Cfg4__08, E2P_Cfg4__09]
BO_ 2483482264 E2P_Cfg4__08: 8 ETH
 SG_ E2P_Cfg4_HW_Ver_Byte9 : 0|8@1+ (1,0) [0|255] ""  PC
 SG_ E2P_Cfg4_HW_Ver_Byte10 : 8|8@1+ (1,0) [0|255] ""  PC
 SG_ E2P_Cfg4_HW_Ver_Byte11 : 16|8@1+ (1,0) [0|255] ""  PC
 SG_ E2P_Cfg4_HW_Ver_Byte12 : 24|8@1+ (1,0) [0|255] ""  PC
 SG_ E2P_Cfg4_HW_Ver_Byte13 : 32|8@1+ (1,0) [0|255] ""  PC
 SG_ E2P_Cfg4_HW_Ver_Byte14 : 40|8@1+ (1,0) [0|255] ""  PC
 SG_ E2P_Cfg4_HW_Ver_Byte15 : 48|8@1+ (1,0) [0|255] ""  PC
 SG_ E2P_Cfg4_HW_Ver_Byte16 : 56|8@1+ (1,0) [0|255] ""  PC

BO_ 2483482265 E2P_Cfg4__09: 8 ETH
 SG_ E2P_Cfg4_HW_Ver_Byte9 : 0|8@1+ (1,0) [0|255] ""  PC
 SG_ E2P_Cfg4_HW_Ver_Byte10 : 8|8@1+ (1,0) [0|255] ""  PC
 SG_ E2P_Cfg4_HW_Ver_Byte11 : 16|8@1+ (1,0) [0|255] ""  PC
 SG_ E2P_Cfg4_HW_Ver_Byte12 : 24|8@1+ (1,0) [0|255] ""  PC
 SG_ E2P_Cfg4_HW_Ver_Byte13 : 32|8@1+ (1,0) [0|255] ""  PC
 SG_ E2P_Cfg4_HW_Ver_Byte14 : 40|8@1+ (1,0) [0|255] ""  PC
 SG_ E2P_Cfg4_HW_Ver_Byte15 : 48|8@1+ (1,0) [0|255] ""  PC
 SG_ E2P_Cfg4_HW_Ver_Byte16 : 56|8@1+ (1,0) [0|255] ""  PC

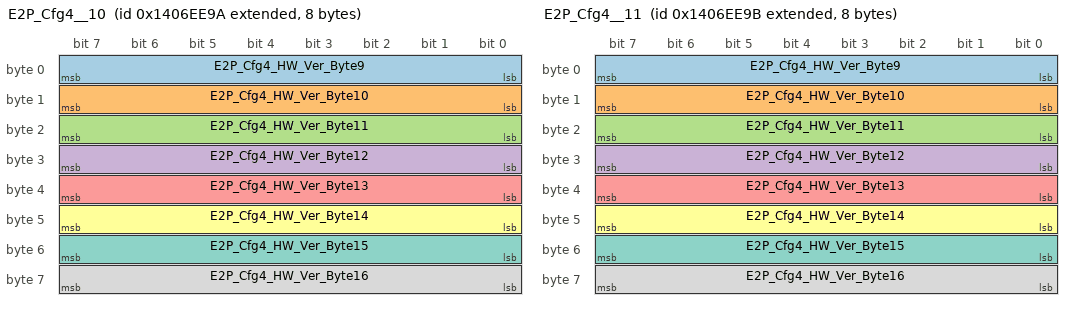
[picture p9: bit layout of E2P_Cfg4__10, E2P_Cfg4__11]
BO_ 2483482266 E2P_Cfg4__10: 8 ETH
 SG_ E2P_Cfg4_HW_Ver_Byte9 : 0|8@1+ (1,0) [0|255] ""  PC
 SG_ E2P_Cfg4_HW_Ver_Byte10 : 8|8@1+ (1,0) [0|255] ""  PC
 SG_ E2P_Cfg4_HW_Ver_Byte11 : 16|8@1+ (1,0) [0|255] ""  PC
 SG_ E2P_Cfg4_HW_Ver_Byte12 : 24|8@1+ (1,0) [0|255] ""  PC
 SG_ E2P_Cfg4_HW_Ver_Byte13 : 32|8@1+ (1,0) [0|255] ""  PC
 SG_ E2P_Cfg4_HW_Ver_Byte14 : 40|8@1+ (1,0) [0|255] ""  PC
 SG_ E2P_Cfg4_HW_Ver_Byte15 : 48|8@1+ (1,0) [0|255] ""  PC
 SG_ E2P_Cfg4_HW_Ver_Byte16 : 56|8@1+ (1,0) [0|255] ""  PC

BO_ 2483482267 E2P_Cfg4__11: 8 ETH
 SG_ E2P_Cfg4_HW_Ver_Byte9 : 0|8@1+ (1,0) [0|255] ""  PC
 SG_ E2P_Cfg4_HW_Ver_Byte10 : 8|8@1+ (1,0) [0|255] ""  PC
 SG_ E2P_Cfg4_HW_Ver_Byte11 : 16|8@1+ (1,0) [0|255] ""  PC
 SG_ E2P_Cfg4_HW_Ver_Byte12 : 24|8@1+ (1,0) [0|255] ""  PC
 SG_ E2P_Cfg4_HW_Ver_Byte13 : 32|8@1+ (1,0) [0|255] ""  PC
 SG_ E2P_Cfg4_HW_Ver_Byte14 : 40|8@1+ (1,0) [0|255] ""  PC
 SG_ E2P_Cfg4_HW_Ver_Byte15 : 48|8@1+ (1,0) [0|255] ""  PC
 SG_ E2P_Cfg4_HW_Ver_Byte16 : 56|8@1+ (1,0) [0|255] ""  PC

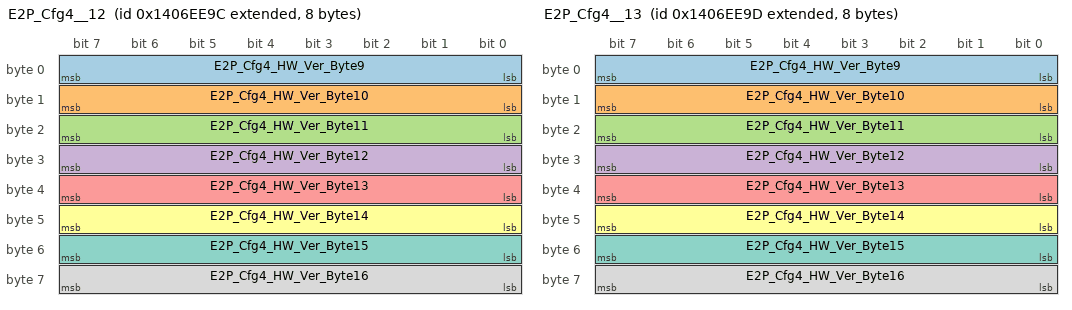
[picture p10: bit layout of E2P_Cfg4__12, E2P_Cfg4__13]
BO_ 2483482268 E2P_Cfg4__12: 8 ETH
 SG_ E2P_Cfg4_HW_Ver_Byte9 : 0|8@1+ (1,0) [0|255] ""  PC
 SG_ E2P_Cfg4_HW_Ver_Byte10 : 8|8@1+ (1,0) [0|255] ""  PC
 SG_ E2P_Cfg4_HW_Ver_Byte11 : 16|8@1+ (1,0) [0|255] ""  PC
 SG_ E2P_Cfg4_HW_Ver_Byte12 : 24|8@1+ (1,0) [0|255] ""  PC
 SG_ E2P_Cfg4_HW_Ver_Byte13 : 32|8@1+ (1,0) [0|255] ""  PC
 SG_ E2P_Cfg4_HW_Ver_Byte14 : 40|8@1+ (1,0) [0|255] ""  PC
 SG_ E2P_Cfg4_HW_Ver_Byte15 : 48|8@1+ (1,0) [0|255] ""  PC
 SG_ E2P_Cfg4_HW_Ver_Byte16 : 56|8@1+ (1,0) [0|255] ""  PC

BO_ 2483482269 E2P_Cfg4__13: 8 ETH
 SG_ E2P_Cfg4_HW_Ver_Byte9 : 0|8@1+ (1,0) [0|255] ""  PC
 SG_ E2P_Cfg4_HW_Ver_Byte10 : 8|8@1+ (1,0) [0|255] ""  PC
 SG_ E2P_Cfg4_HW_Ver_Byte11 : 16|8@1+ (1,0) [0|255] ""  PC
 SG_ E2P_Cfg4_HW_Ver_Byte12 : 24|8@1+ (1,0) [0|255] ""  PC
 SG_ E2P_Cfg4_HW_Ver_Byte13 : 32|8@1+ (1,0) [0|255] ""  PC
 SG_ E2P_Cfg4_HW_Ver_Byte14 : 40|8@1+ (1,0) [0|255] ""  PC
 SG_ E2P_Cfg4_HW_Ver_Byte15 : 48|8@1+ (1,0) [0|255] ""  PC
 SG_ E2P_Cfg4_HW_Ver_Byte16 : 56|8@1+ (1,0) [0|255] ""  PC

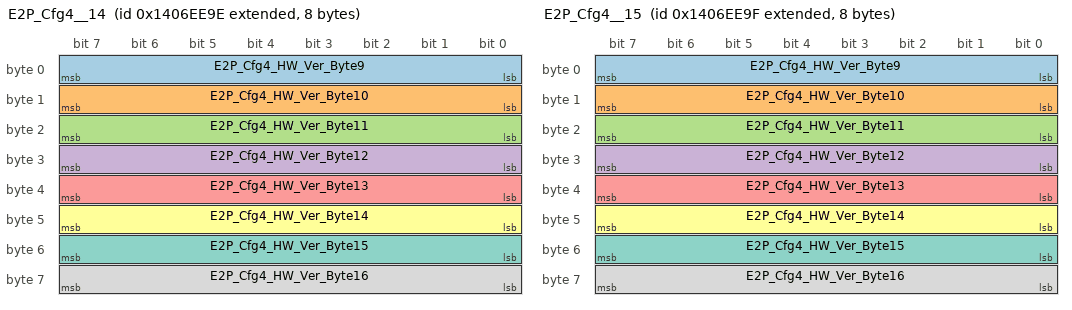
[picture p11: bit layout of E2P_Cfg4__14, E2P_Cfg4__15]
BO_ 2483482270 E2P_Cfg4__14: 8 ETH
 SG_ E2P_Cfg4_HW_Ver_Byte9 : 0|8@1+ (1,0) [0|255] ""  PC
 SG_ E2P_Cfg4_HW_Ver_Byte10 : 8|8@1+ (1,0) [0|255] ""  PC
 SG_ E2P_Cfg4_HW_Ver_Byte11 : 16|8@1+ (1,0) [0|255] ""  PC
 SG_ E2P_Cfg4_HW_Ver_Byte12 : 24|8@1+ (1,0) [0|255] ""  PC
 SG_ E2P_Cfg4_HW_Ver_Byte13 : 32|8@1+ (1,0) [0|255] ""  PC
 SG_ E2P_Cfg4_HW_Ver_Byte14 : 40|8@1+ (1,0) [0|255] ""  PC
 SG_ E2P_Cfg4_HW_Ver_Byte15 : 48|8@1+ (1,0) [0|255] ""  PC
 SG_ E2P_Cfg4_HW_Ver_Byte16 : 56|8@1+ (1,0) [0|255] ""  PC

BO_ 2483482271 E2P_Cfg4__15: 8 ETH
 SG_ E2P_Cfg4_HW_Ver_Byte9 : 0|8@1+ (1,0) [0|255] ""  PC
 SG_ E2P_Cfg4_HW_Ver_Byte10 : 8|8@1+ (1,0) [0|255] ""  PC
 SG_ E2P_Cfg4_HW_Ver_Byte11 : 16|8@1+ (1,0) [0|255] ""  PC
 SG_ E2P_Cfg4_HW_Ver_Byte12 : 24|8@1+ (1,0) [0|255] ""  PC
 SG_ E2P_Cfg4_HW_Ver_Byte13 : 32|8@1+ (1,0) [0|255] ""  PC
 SG_ E2P_Cfg4_HW_Ver_Byte14 : 40|8@1+ (1,0) [0|255] ""  PC
 SG_ E2P_Cfg4_HW_Ver_Byte15 : 48|8@1+ (1,0) [0|255] ""  PC
 SG_ E2P_Cfg4_HW_Ver_Byte16 : 56|8@1+ (1,0) [0|255] ""  PC

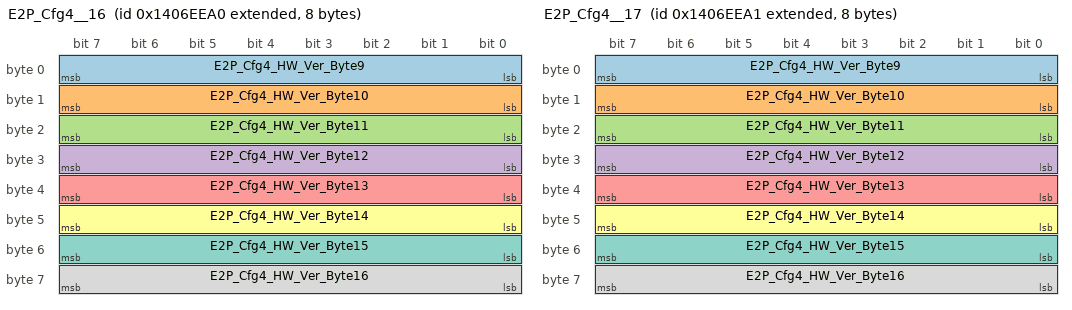
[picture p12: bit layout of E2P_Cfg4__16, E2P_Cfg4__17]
BO_ 2483482272 E2P_Cfg4__16: 8 ETH
 SG_ E2P_Cfg4_HW_Ver_Byte9 : 0|8@1+ (1,0) [0|255] ""  PC
 SG_ E2P_Cfg4_HW_Ver_Byte10 : 8|8@1+ (1,0) [0|255] ""  PC
 SG_ E2P_Cfg4_HW_Ver_Byte11 : 16|8@1+ (1,0) [0|255] ""  PC
 SG_ E2P_Cfg4_HW_Ver_Byte12 : 24|8@1+ (1,0) [0|255] ""  PC
 SG_ E2P_Cfg4_HW_Ver_Byte13 : 32|8@1+ (1,0) [0|255] ""  PC
 SG_ E2P_Cfg4_HW_Ver_Byte14 : 40|8@1+ (1,0) [0|255] ""  PC
 SG_ E2P_Cfg4_HW_Ver_Byte15 : 48|8@1+ (1,0) [0|255] ""  PC
 SG_ E2P_Cfg4_HW_Ver_Byte16 : 56|8@1+ (1,0) [0|255] ""  PC

BO_ 2483482273 E2P_Cfg4__17: 8 ETH
 SG_ E2P_Cfg4_HW_Ver_Byte9 : 0|8@1+ (1,0) [0|255] ""  PC
 SG_ E2P_Cfg4_HW_Ver_Byte10 : 8|8@1+ (1,0) [0|255] ""  PC
 SG_ E2P_Cfg4_HW_Ver_Byte11 : 16|8@1+ (1,0) [0|255] ""  PC
 SG_ E2P_Cfg4_HW_Ver_Byte12 : 24|8@1+ (1,0) [0|255] ""  PC
 SG_ E2P_Cfg4_HW_Ver_Byte13 : 32|8@1+ (1,0) [0|255] ""  PC
 SG_ E2P_Cfg4_HW_Ver_Byte14 : 40|8@1+ (1,0) [0|255] ""  PC
 SG_ E2P_Cfg4_HW_Ver_Byte15 : 48|8@1+ (1,0) [0|255] ""  PC
 SG_ E2P_Cfg4_HW_Ver_Byte16 : 56|8@1+ (1,0) [0|255] ""  PC

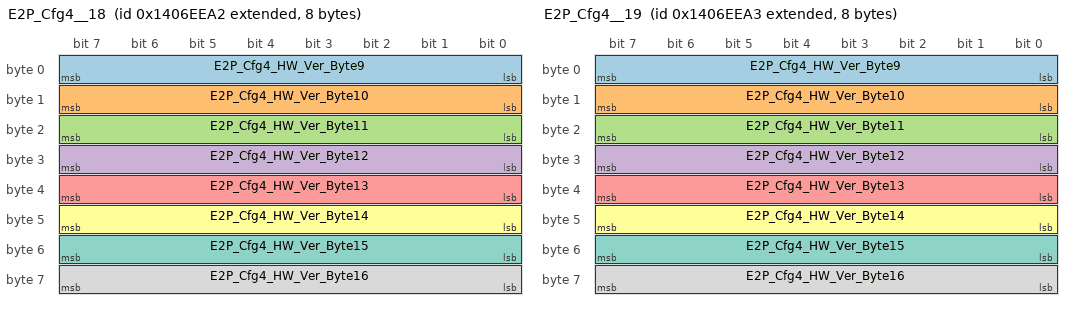
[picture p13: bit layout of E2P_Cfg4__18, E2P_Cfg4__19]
BO_ 2483482274 E2P_Cfg4__18: 8 ETH
 SG_ E2P_Cfg4_HW_Ver_Byte9 : 0|8@1+ (1,0) [0|255] ""  PC
 SG_ E2P_Cfg4_HW_Ver_Byte10 : 8|8@1+ (1,0) [0|255] ""  PC
 SG_ E2P_Cfg4_HW_Ver_Byte11 : 16|8@1+ (1,0) [0|255] ""  PC
 SG_ E2P_Cfg4_HW_Ver_Byte12 : 24|8@1+ (1,0) [0|255] ""  PC
 SG_ E2P_Cfg4_HW_Ver_Byte13 : 32|8@1+ (1,0) [0|255] ""  PC
 SG_ E2P_Cfg4_HW_Ver_Byte14 : 40|8@1+ (1,0) [0|255] ""  PC
 SG_ E2P_Cfg4_HW_Ver_Byte15 : 48|8@1+ (1,0) [0|255] ""  PC
 SG_ E2P_Cfg4_HW_Ver_Byte16 : 56|8@1+ (1,0) [0|255] ""  PC

BO_ 2483482275 E2P_Cfg4__19: 8 ETH
 SG_ E2P_Cfg4_HW_Ver_Byte9 : 0|8@1+ (1,0) [0|255] ""  PC
 SG_ E2P_Cfg4_HW_Ver_Byte10 : 8|8@1+ (1,0) [0|255] ""  PC
 SG_ E2P_Cfg4_HW_Ver_Byte11 : 16|8@1+ (1,0) [0|255] ""  PC
 SG_ E2P_Cfg4_HW_Ver_Byte12 : 24|8@1+ (1,0) [0|255] ""  PC
 SG_ E2P_Cfg4_HW_Ver_Byte13 : 32|8@1+ (1,0) [0|255] ""  PC
 SG_ E2P_Cfg4_HW_Ver_Byte14 : 40|8@1+ (1,0) [0|255] ""  PC
 SG_ E2P_Cfg4_HW_Ver_Byte15 : 48|8@1+ (1,0) [0|255] ""  PC
 SG_ E2P_Cfg4_HW_Ver_Byte16 : 56|8@1+ (1,0) [0|255] ""  PC

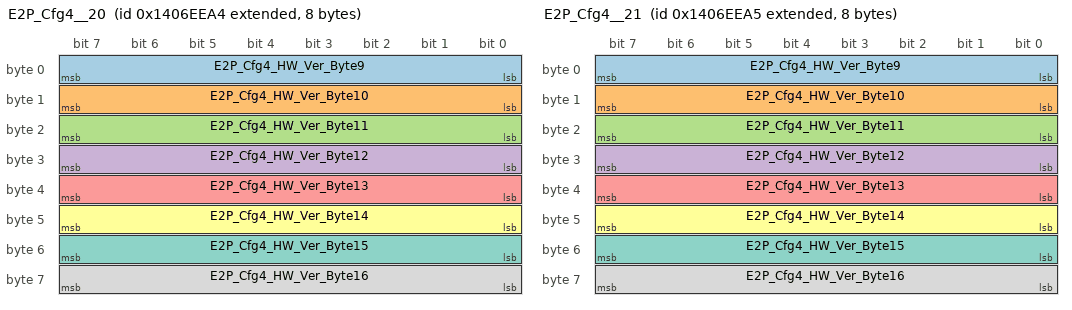
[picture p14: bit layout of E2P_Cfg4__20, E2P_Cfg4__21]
BO_ 2483482276 E2P_Cfg4__20: 8 ETH
 SG_ E2P_Cfg4_HW_Ver_Byte9 : 0|8@1+ (1,0) [0|255] ""  PC
 SG_ E2P_Cfg4_HW_Ver_Byte10 : 8|8@1+ (1,0) [0|255] ""  PC
 SG_ E2P_Cfg4_HW_Ver_Byte11 : 16|8@1+ (1,0) [0|255] ""  PC
 SG_ E2P_Cfg4_HW_Ver_Byte12 : 24|8@1+ (1,0) [0|255] ""  PC
 SG_ E2P_Cfg4_HW_Ver_Byte13 : 32|8@1+ (1,0) [0|255] ""  PC
 SG_ E2P_Cfg4_HW_Ver_Byte14 : 40|8@1+ (1,0) [0|255] ""  PC
 SG_ E2P_Cfg4_HW_Ver_Byte15 : 48|8@1+ (1,0) [0|255] ""  PC
 SG_ E2P_Cfg4_HW_Ver_Byte16 : 56|8@1+ (1,0) [0|255] ""  PC

BO_ 2483482277 E2P_Cfg4__21: 8 ETH
 SG_ E2P_Cfg4_HW_Ver_Byte9 : 0|8@1+ (1,0) [0|255] ""  PC
 SG_ E2P_Cfg4_HW_Ver_Byte10 : 8|8@1+ (1,0) [0|255] ""  PC
 SG_ E2P_Cfg4_HW_Ver_Byte11 : 16|8@1+ (1,0) [0|255] ""  PC
 SG_ E2P_Cfg4_HW_Ver_Byte12 : 24|8@1+ (1,0) [0|255] ""  PC
 SG_ E2P_Cfg4_HW_Ver_Byte13 : 32|8@1+ (1,0) [0|255] ""  PC
 SG_ E2P_Cfg4_HW_Ver_Byte14 : 40|8@1+ (1,0) [0|255] ""  PC
 SG_ E2P_Cfg4_HW_Ver_Byte15 : 48|8@1+ (1,0) [0|255] ""  PC
 SG_ E2P_Cfg4_HW_Ver_Byte16 : 56|8@1+ (1,0) [0|255] ""  PC

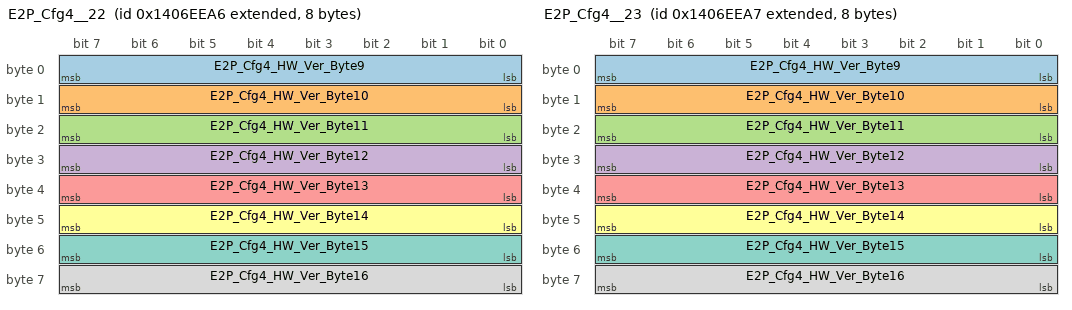
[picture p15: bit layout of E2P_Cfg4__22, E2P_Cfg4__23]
BO_ 2483482278 E2P_Cfg4__22: 8 ETH
 SG_ E2P_Cfg4_HW_Ver_Byte9 : 0|8@1+ (1,0) [0|255] ""  PC
 SG_ E2P_Cfg4_HW_Ver_Byte10 : 8|8@1+ (1,0) [0|255] ""  PC
 SG_ E2P_Cfg4_HW_Ver_Byte11 : 16|8@1+ (1,0) [0|255] ""  PC
 SG_ E2P_Cfg4_HW_Ver_Byte12 : 24|8@1+ (1,0) [0|255] ""  PC
 SG_ E2P_Cfg4_HW_Ver_Byte13 : 32|8@1+ (1,0) [0|255] ""  PC
 SG_ E2P_Cfg4_HW_Ver_Byte14 : 40|8@1+ (1,0) [0|255] ""  PC
 SG_ E2P_Cfg4_HW_Ver_Byte15 : 48|8@1+ (1,0) [0|255] ""  PC
 SG_ E2P_Cfg4_HW_Ver_Byte16 : 56|8@1+ (1,0) [0|255] ""  PC

BO_ 2483482279 E2P_Cfg4__23: 8 ETH
 SG_ E2P_Cfg4_HW_Ver_Byte9 : 0|8@1+ (1,0) [0|255] ""  PC
 SG_ E2P_Cfg4_HW_Ver_Byte10 : 8|8@1+ (1,0) [0|255] ""  PC
 SG_ E2P_Cfg4_HW_Ver_Byte11 : 16|8@1+ (1,0) [0|255] ""  PC
 SG_ E2P_Cfg4_HW_Ver_Byte12 : 24|8@1+ (1,0) [0|255] ""  PC
 SG_ E2P_Cfg4_HW_Ver_Byte13 : 32|8@1+ (1,0) [0|255] ""  PC
 SG_ E2P_Cfg4_HW_Ver_Byte14 : 40|8@1+ (1,0) [0|255] ""  PC
 SG_ E2P_Cfg4_HW_Ver_Byte15 : 48|8@1+ (1,0) [0|255] ""  PC
 SG_ E2P_Cfg4_HW_Ver_Byte16 : 56|8@1+ (1,0) [0|255] ""  PC

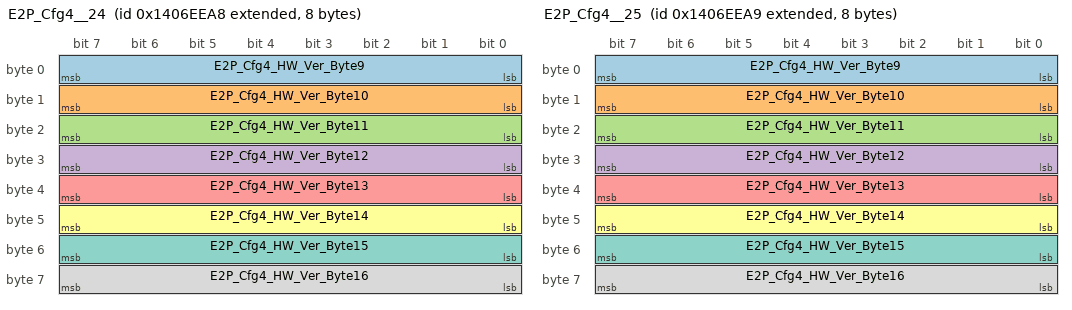
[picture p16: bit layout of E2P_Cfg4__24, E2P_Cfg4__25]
BO_ 2483482280 E2P_Cfg4__24: 8 ETH
 SG_ E2P_Cfg4_HW_Ver_Byte9 : 0|8@1+ (1,0) [0|255] ""  PC
 SG_ E2P_Cfg4_HW_Ver_Byte10 : 8|8@1+ (1,0) [0|255] ""  PC
 SG_ E2P_Cfg4_HW_Ver_Byte11 : 16|8@1+ (1,0) [0|255] ""  PC
 SG_ E2P_Cfg4_HW_Ver_Byte12 : 24|8@1+ (1,0) [0|255] ""  PC
 SG_ E2P_Cfg4_HW_Ver_Byte13 : 32|8@1+ (1,0) [0|255] ""  PC
 SG_ E2P_Cfg4_HW_Ver_Byte14 : 40|8@1+ (1,0) [0|255] ""  PC
 SG_ E2P_Cfg4_HW_Ver_Byte15 : 48|8@1+ (1,0) [0|255] ""  PC
 SG_ E2P_Cfg4_HW_Ver_Byte16 : 56|8@1+ (1,0) [0|255] ""  PC

BO_ 2483482281 E2P_Cfg4__25: 8 ETH
 SG_ E2P_Cfg4_HW_Ver_Byte9 : 0|8@1+ (1,0) [0|255] ""  PC
 SG_ E2P_Cfg4_HW_Ver_Byte10 : 8|8@1+ (1,0) [0|255] ""  PC
 SG_ E2P_Cfg4_HW_Ver_Byte11 : 16|8@1+ (1,0) [0|255] ""  PC
 SG_ E2P_Cfg4_HW_Ver_Byte12 : 24|8@1+ (1,0) [0|255] ""  PC
 SG_ E2P_Cfg4_HW_Ver_Byte13 : 32|8@1+ (1,0) [0|255] ""  PC
 SG_ E2P_Cfg4_HW_Ver_Byte14 : 40|8@1+ (1,0) [0|255] ""  PC
 SG_ E2P_Cfg4_HW_Ver_Byte15 : 48|8@1+ (1,0) [0|255] ""  PC
 SG_ E2P_Cfg4_HW_Ver_Byte16 : 56|8@1+ (1,0) [0|255] ""  PC

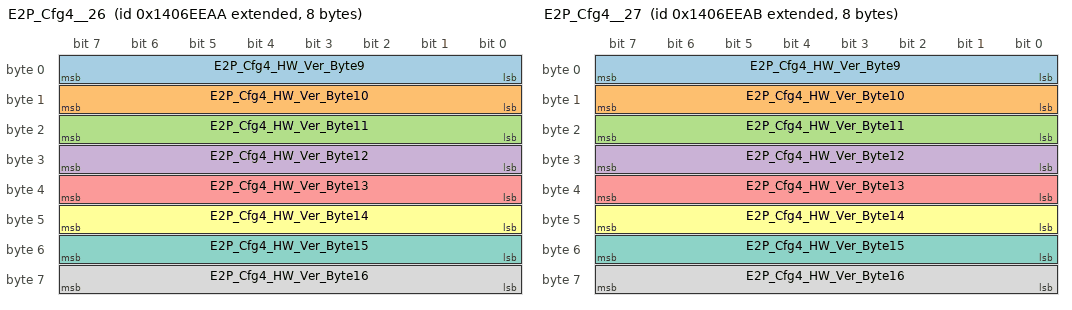
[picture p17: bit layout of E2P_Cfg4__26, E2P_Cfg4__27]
BO_ 2483482282 E2P_Cfg4__26: 8 ETH
 SG_ E2P_Cfg4_HW_Ver_Byte9 : 0|8@1+ (1,0) [0|255] ""  PC
 SG_ E2P_Cfg4_HW_Ver_Byte10 : 8|8@1+ (1,0) [0|255] ""  PC
 SG_ E2P_Cfg4_HW_Ver_Byte11 : 16|8@1+ (1,0) [0|255] ""  PC
 SG_ E2P_Cfg4_HW_Ver_Byte12 : 24|8@1+ (1,0) [0|255] ""  PC
 SG_ E2P_Cfg4_HW_Ver_Byte13 : 32|8@1+ (1,0) [0|255] ""  PC
 SG_ E2P_Cfg4_HW_Ver_Byte14 : 40|8@1+ (1,0) [0|255] ""  PC
 SG_ E2P_Cfg4_HW_Ver_Byte15 : 48|8@1+ (1,0) [0|255] ""  PC
 SG_ E2P_Cfg4_HW_Ver_Byte16 : 56|8@1+ (1,0) [0|255] ""  PC

BO_ 2483482283 E2P_Cfg4__27: 8 ETH
 SG_ E2P_Cfg4_HW_Ver_Byte9 : 0|8@1+ (1,0) [0|255] ""  PC
 SG_ E2P_Cfg4_HW_Ver_Byte10 : 8|8@1+ (1,0) [0|255] ""  PC
 SG_ E2P_Cfg4_HW_Ver_Byte11 : 16|8@1+ (1,0) [0|255] ""  PC
 SG_ E2P_Cfg4_HW_Ver_Byte12 : 24|8@1+ (1,0) [0|255] ""  PC
 SG_ E2P_Cfg4_HW_Ver_Byte13 : 32|8@1+ (1,0) [0|255] ""  PC
 SG_ E2P_Cfg4_HW_Ver_Byte14 : 40|8@1+ (1,0) [0|255] ""  PC
 SG_ E2P_Cfg4_HW_Ver_Byte15 : 48|8@1+ (1,0) [0|255] ""  PC
 SG_ E2P_Cfg4_HW_Ver_Byte16 : 56|8@1+ (1,0) [0|255] ""  PC

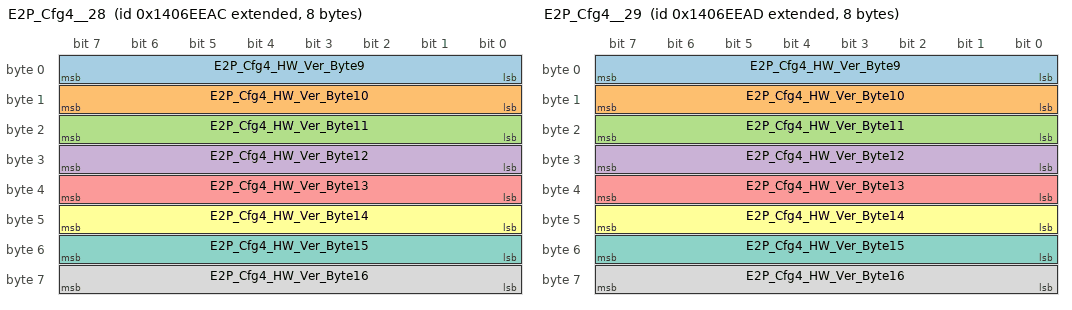
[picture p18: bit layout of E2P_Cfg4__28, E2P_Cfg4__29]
BO_ 2483482284 E2P_Cfg4__28: 8 ETH
 SG_ E2P_Cfg4_HW_Ver_Byte9 : 0|8@1+ (1,0) [0|255] ""  PC
 SG_ E2P_Cfg4_HW_Ver_Byte10 : 8|8@1+ (1,0) [0|255] ""  PC
 SG_ E2P_Cfg4_HW_Ver_Byte11 : 16|8@1+ (1,0) [0|255] ""  PC
 SG_ E2P_Cfg4_HW_Ver_Byte12 : 24|8@1+ (1,0) [0|255] ""  PC
 SG_ E2P_Cfg4_HW_Ver_Byte13 : 32|8@1+ (1,0) [0|255] ""  PC
 SG_ E2P_Cfg4_HW_Ver_Byte14 : 40|8@1+ (1,0) [0|255] ""  PC
 SG_ E2P_Cfg4_HW_Ver_Byte15 : 48|8@1+ (1,0) [0|255] ""  PC
 SG_ E2P_Cfg4_HW_Ver_Byte16 : 56|8@1+ (1,0) [0|255] ""  PC

BO_ 2483482285 E2P_Cfg4__29: 8 ETH
 SG_ E2P_Cfg4_HW_Ver_Byte9 : 0|8@1+ (1,0) [0|255] ""  PC
 SG_ E2P_Cfg4_HW_Ver_Byte10 : 8|8@1+ (1,0) [0|255] ""  PC
 SG_ E2P_Cfg4_HW_Ver_Byte11 : 16|8@1+ (1,0) [0|255] ""  PC
 SG_ E2P_Cfg4_HW_Ver_Byte12 : 24|8@1+ (1,0) [0|255] ""  PC
 SG_ E2P_Cfg4_HW_Ver_Byte13 : 32|8@1+ (1,0) [0|255] ""  PC
 SG_ E2P_Cfg4_HW_Ver_Byte14 : 40|8@1+ (1,0) [0|255] ""  PC
 SG_ E2P_Cfg4_HW_Ver_Byte15 : 48|8@1+ (1,0) [0|255] ""  PC
 SG_ E2P_Cfg4_HW_Ver_Byte16 : 56|8@1+ (1,0) [0|255] ""  PC

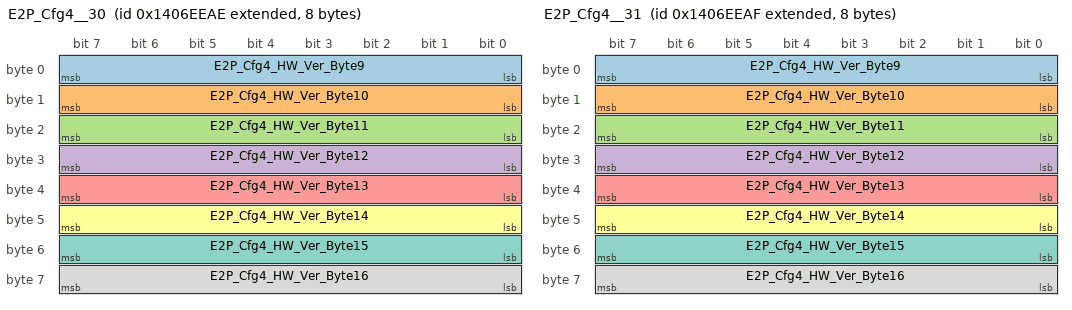
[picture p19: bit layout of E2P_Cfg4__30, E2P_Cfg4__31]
BO_ 2483482286 E2P_Cfg4__30: 8 ETH
 SG_ E2P_Cfg4_HW_Ver_Byte9 : 0|8@1+ (1,0) [0|255] ""  PC
 SG_ E2P_Cfg4_HW_Ver_Byte10 : 8|8@1+ (1,0) [0|255] ""  PC
 SG_ E2P_Cfg4_HW_Ver_Byte11 : 16|8@1+ (1,0) [0|255] ""  PC
 SG_ E2P_Cfg4_HW_Ver_Byte12 : 24|8@1+ (1,0) [0|255] ""  PC
 SG_ E2P_Cfg4_HW_Ver_Byte13 : 32|8@1+ (1,0) [0|255] ""  PC
 SG_ E2P_Cfg4_HW_Ver_Byte14 : 40|8@1+ (1,0) [0|255] ""  PC
 SG_ E2P_Cfg4_HW_Ver_Byte15 : 48|8@1+ (1,0) [0|255] ""  PC
 SG_ E2P_Cfg4_HW_Ver_Byte16 : 56|8@1+ (1,0) [0|255] ""  PC

BO_ 2483482287 E2P_Cfg4__31: 8 ETH
 SG_ E2P_Cfg4_HW_Ver_Byte9 : 0|8@1+ (1,0) [0|255] ""  PC
 SG_ E2P_Cfg4_HW_Ver_Byte10 : 8|8@1+ (1,0) [0|255] ""  PC
 SG_ E2P_Cfg4_HW_Ver_Byte11 : 16|8@1+ (1,0) [0|255] ""  PC
 SG_ E2P_Cfg4_HW_Ver_Byte12 : 24|8@1+ (1,0) [0|255] ""  PC
 SG_ E2P_Cfg4_HW_Ver_Byte13 : 32|8@1+ (1,0) [0|255] ""  PC
 SG_ E2P_Cfg4_HW_Ver_Byte14 : 40|8@1+ (1,0) [0|255] ""  PC
 SG_ E2P_Cfg4_HW_Ver_Byte15 : 48|8@1+ (1,0) [0|255] ""  PC
 SG_ E2P_Cfg4_HW_Ver_Byte16 : 56|8@1+ (1,0) [0|255] ""  PC

BO_ 2165465583 L2S_CMD1: 8 LEMS
 SG_ L2S_CMD1_CellHeatModeRequ1 : 0|1@1+ (1,0) [0|1] ""  SBMU
 SG_ L2S_CMD1_CellHeatModeRequ2 : 1|1@1+ (1,0) [0|1] ""  SBMU
 SG_ L2S_CMD1_CellHeatModeRequ3 : 2|1@1+ (1,0) [0|1] ""  SBMU
 SG_ L2S_CMD1_Reserve : 3|61@1+ (1,0) [0|2.30584300921369E+018] ""  SBMU

BO_ 2333671233 S2A_SUMDATA18__01: 8 SBMU
 SG_ S2A_BAT_I_HVS_01 : 0|16@1+ (0.1,-2000) [-2000|4553.5] "A"  MBMU,PC
 SG_ BAT_U_HVS_01 : 16|16@1+ (0.1,0) [0|6553.5] "V"  MBMU,PC
 SG_ BAT_U_TOT_HVS_01 : 32|16@1+ (0.1,0) [0|6553.5] "V"  MBMU,PC

BO_ 2333671234 S2A_SUMDATA18__02: 8 SBMU
 SG_ S2A_BAT_I_HVS_02 : 0|16@1+ (0.1,-2000) [-2000|4553.5] "A"  MBMU,PC
 SG_ BAT_U_HVS_02 : 16|16@1+ (0.1,0) [0|6553.5] "V"  MBMU,PC
 SG_ BAT_U_TOT_HVS_02 : 32|16@1+ (0.1,0) [0|6553.5] "V"  MBMU,PC

BO_ 2333671235 S2A_SUMDATA18__03: 8 SBMU
 SG_ S2A_BAT_I_HVS_03 : 0|16@1+ (0.1,-2000) [-2000|4553.5] "A"  MBMU,PC
 SG_ BAT_U_HVS_03 : 16|16@1+ (0.1,0) [0|6553.5] "V"  MBMU,PC
 SG_ BAT_U_TOT_HVS_03 : 32|16@1+ (0.1,0) [0|6553.5] "V"  MBMU,PC

BO_ 2333671236 S2A_SUMDATA18__04: 8 SBMU
 SG_ S2A_BAT_I_HVS_04 : 0|16@1+ (0.1,-2000) [-2000|4553.5] "A"  MBMU,PC
 SG_ BAT_U_HVS_04 : 16|16@1+ (0.1,0) [0|6553.5] "V"  MBMU,PC
 SG_ BAT_U_TOT_HVS_04 : 32|16@1+ (0.1,0) [0|6553.5] "V"  MBMU,PC

BO_ 2333671237 S2A_SUMDATA18__05: 8 SBMU
 SG_ S2A_BAT_I_HVS_05 : 0|16@1+ (0.1,-2000) [-2000|4553.5] "A"  MBMU,PC
 SG_ BAT_U_HVS_05 : 16|16@1+ (0.1,0) [0|6553.5] "V"  MBMU,PC
 SG_ BAT_U_TOT_HVS_05 : 32|16@1+ (0.1,0) [0|6553.5] "V"  MBMU,PC

BO_ 2333671238 S2A_SUMDATA18__06: 8 SBMU
 SG_ S2A_BAT_I_HVS_06 : 0|16@1+ (0.1,-2000) [-2000|4553.5] "A"  MBMU,PC
 SG_ BAT_U_HVS_06 : 16|16@1+ (0.1,0) [0|6553.5] "V"  MBMU,PC
 SG_ BAT_U_TOT_HVS_06 : 32|16@1+ (0.1,0) [0|6553.5] "V"  MBMU,PC

BO_ 2333671239 S2A_SUMDATA18__07: 8 SBMU
 SG_ S2A_BAT_I_HVS_07 : 0|16@1+ (0.1,-2000) [-2000|4553.5] "A"  MBMU,PC
 SG_ BAT_U_HVS_07 : 16|16@1+ (0.1,0) [0|6553.5] "V"  MBMU,PC
 SG_ BAT_U_TOT_HVS_07 : 32|16@1+ (0.1,0) [0|6553.5] "V"  MBMU,PC

BO_ 2333671240 S2A_SUMDATA18__08: 8 SBMU
 SG_ S2A_BAT_I_HVS_08 : 0|16@1+ (0.1,-2000) [-2000|4553.5] "A"  MBMU,PC
 SG_ BAT_U_HVS_08 : 16|16@1+ (0.1,0) [0|6553.5] "V"  MBMU,PC
 SG_ BAT_U_TOT_HVS_08 : 32|16@1+ (0.1,0) [0|6553.5] "V"  MBMU,PC

BO_ 2333671241 S2A_SUMDATA18__09: 8 SBMU
 SG_ S2A_BAT_I_HVS_09 : 0|16@1+ (0.1,-2000) [-2000|4553.5] "A"  MBMU,PC
 SG_ BAT_U_HVS_09 : 16|16@1+ (0.1,0) [0|6553.5] "V"  MBMU,PC
 SG_ BAT_U_TOT_HVS_09 : 32|16@1+ (0.1,0) [0|6553.5] "V"  MBMU,PC

BO_ 2333671242 S2A_SUMDATA18__10: 8 SBMU
 SG_ S2A_BAT_I_HVS_10 : 0|16@1+ (0.1,-2000) [-2000|4553.5] "A"  MBMU,PC
 SG_ BAT_U_HVS_10 : 16|16@1+ (0.1,0) [0|6553.5] "V"  MBMU,PC
 SG_ BAT_U_TOT_HVS_10 : 32|16@1+ (0.1,0) [0|6553.5] "V"  MBMU,PC

BO_ 2333671243 S2A_SUMDATA18__11: 8 SBMU
 SG_ S2A_BAT_I_HVS_11 : 0|16@1+ (0.1,-2000) [-2000|4553.5] "A"  MBMU,PC
 SG_ BAT_U_HVS_11 : 16|16@1+ (0.1,0) [0|6553.5] "V"  MBMU,PC
 SG_ BAT_U_TOT_HVS_11 : 32|16@1+ (0.1,0) [0|6553.5] "V"  MBMU,PC

BO_ 2333671244 S2A_SUMDATA18__12: 8 SBMU
 SG_ S2A_BAT_I_HVS_12 : 0|16@1+ (0.1,-2000) [-2000|4553.5] "A"  MBMU,PC
 SG_ BAT_U_HVS_12 : 16|16@1+ (0.1,0) [0|6553.5] "V"  MBMU,PC
 SG_ BAT_U_TOT_HVS_12 : 32|16@1+ (0.1,0) [0|6553.5] "V"  MBMU,PC

BO_ 2333671245 S2A_SUMDATA18__13: 8 SBMU
 SG_ S2A_BAT_I_HVS_13 : 0|16@1+ (0.1,-2000) [-2000|4553.5] "A"  MBMU,PC
 SG_ BAT_U_HVS_13 : 16|16@1+ (0.1,0) [0|6553.5] "V"  MBMU,PC
 SG_ BAT_U_TOT_HVS_13 : 32|16@1+ (0.1,0) [0|6553.5] "V"  MBMU,PC

BO_ 2333671246 S2A_SUMDATA18__14: 8 SBMU
 SG_ S2A_BAT_I_HVS_14 : 0|16@1+ (0.1,-2000) [-2000|4553.5] "A"  MBMU,PC
 SG_ BAT_U_HVS_14 : 16|16@1+ (0.1,0) [0|6553.5] "V"  MBMU,PC
 SG_ BAT_U_TOT_HVS_14 : 32|16@1+ (0.1,0) [0|6553.5] "V"  MBMU,PC

BO_ 2333671247 S2A_SUMDATA18__15: 8 SBMU
 SG_ S2A_BAT_I_HVS_15 : 0|16@1+ (0.1,-2000) [-2000|4553.5] "A"  MBMU,PC
 SG_ BAT_U_HVS_15 : 16|16@1+ (0.1,0) [0|6553.5] "V"  MBMU,PC
 SG_ BAT_U_TOT_HVS_15 : 32|16@1+ (0.1,0) [0|6553.5] "V"  MBMU,PC

BO_ 2333671248 S2A_SUMDATA18__16: 8 SBMU
 SG_ S2A_BAT_I_HVS_16 : 0|16@1+ (0.1,-2000) [-2000|4553.5] "A"  MBMU,PC
 SG_ BAT_U_HVS_16 : 16|16@1+ (0.1,0) [0|6553.5] "V"  MBMU,PC
 SG_ BAT_U_TOT_HVS_16 : 32|16@1+ (0.1,0) [0|6553.5] "V"  MBMU,PC

BO_ 2333671249 S2A_SUMDATA18__17: 8 SBMU
 SG_ S2A_BAT_I_HVS_17 : 0|16@1+ (0.1,-2000) [-2000|4553.5] "A"  MBMU,PC
 SG_ BAT_U_HVS_17 : 16|16@1+ (0.1,0) [0|6553.5] "V"  MBMU,PC
 SG_ BAT_U_TOT_HVS_17 : 32|16@1+ (0.1,0) [0|6553.5] "V"  MBMU,PC

BO_ 2333671250 S2A_SUMDATA18__18: 8 SBMU
 SG_ S2A_BAT_I_HVS_18 : 0|16@1+ (0.1,-2000) [-2000|4553.5] "A"  MBMU,PC
 SG_ BAT_U_HVS_18 : 16|16@1+ (0.1,0) [0|6553.5] "V"  MBMU,PC
 SG_ BAT_U_TOT_HVS_18 : 32|16@1+ (0.1,0) [0|6553.5] "V"  MBMU,PC

BO_ 2333671251 S2A_SUMDATA18__19: 8 SBMU
 SG_ S2A_BAT_I_HVS_19 : 0|16@1+ (0.1,-2000) [-2000|4553.5] "A"  MBMU,PC
 SG_ BAT_U_HVS_19 : 16|16@1+ (0.1,0) [0|6553.5] "V"  MBMU,PC
 SG_ BAT_U_TOT_HVS_19 : 32|16@1+ (0.1,0) [0|6553.5] "V"  MBMU,PC

BO_ 2333671252 S2A_SUMDATA18__20: 8 SBMU
 SG_ S2A_BAT_I_HVS_20 : 0|16@1+ (0.1,-2000) [-2000|4553.5] "A"  MBMU,PC
 SG_ BAT_U_HVS_20 : 16|16@1+ (0.1,0) [0|6553.5] "V"  MBMU,PC
 SG_ BAT_U_TOT_HVS_20 : 32|16@1+ (0.1,0) [0|6553.5] "V"  MBMU,PC

BO_ 2333671253 S2A_SUMDATA18__21: 8 SBMU
 SG_ S2A_BAT_I_HVS_21 : 0|16@1+ (0.1,-2000) [-2000|4553.5] "A"  MBMU,PC
 SG_ BAT_U_HVS_21 : 16|16@1+ (0.1,0) [0|6553.5] "V"  MBMU,PC
 SG_ BAT_U_TOT_HVS_21 : 32|16@1+ (0.1,0) [0|6553.5] "V"  MBMU,PC

BO_ 2333671254 S2A_SUMDATA18__22: 8 SBMU
 SG_ S2A_BAT_I_HVS_22 : 0|16@1+ (0.1,-2000) [-2000|4553.5] "A"  MBMU,PC
 SG_ BAT_U_HVS_22 : 16|16@1+ (0.1,0) [0|6553.5] "V"  MBMU,PC
 SG_ BAT_U_TOT_HVS_22 : 32|16@1+ (0.1,0) [0|6553.5] "V"  MBMU,PC

BO_ 2333671255 S2A_SUMDATA18__23: 8 SBMU
 SG_ S2A_BAT_I_HVS_23 : 0|16@1+ (0.1,-2000) [-2000|4553.5] "A"  MBMU,PC
 SG_ BAT_U_HVS_23 : 16|16@1+ (0.1,0) [0|6553.5] "V"  MBMU,PC
 SG_ BAT_U_TOT_HVS_23 : 32|16@1+ (0.1,0) [0|6553.5] "V"  MBMU,PC

BO_ 2333671256 S2A_SUMDATA18__24: 8 SBMU
 SG_ S2A_BAT_I_HVS_24 : 0|16@1+ (0.1,-2000) [-2000|4553.5] "A"  MBMU,PC
 SG_ BAT_U_HVS_24 : 16|16@1+ (0.1,0) [0|6553.5] "V"  MBMU,PC
 SG_ BAT_U_TOT_HVS_24 : 32|16@1+ (0.1,0) [0|6553.5] "V"  MBMU,PC

BO_ 2333671257 S2A_SUMDATA18__25: 8 SBMU
 SG_ S2A_BAT_I_HVS_25 : 0|16@1+ (0.1,-2000) [-2000|4553.5] "A"  MBMU,PC
 SG_ BAT_U_HVS_25 : 16|16@1+ (0.1,0) [0|6553.5] "V"  MBMU,PC
 SG_ BAT_U_TOT_HVS_25 : 32|16@1+ (0.1,0) [0|6553.5] "V"  MBMU,PC

BO_ 2333671258 S2A_SUMDATA18__26: 8 SBMU
 SG_ S2A_BAT_I_HVS_26 : 0|16@1+ (0.1,-2000) [-2000|4553.5] "A"  MBMU,PC
 SG_ BAT_U_HVS_26 : 16|16@1+ (0.1,0) [0|6553.5] "V"  MBMU,PC
 SG_ BAT_U_TOT_HVS_26 : 32|16@1+ (0.1,0) [0|6553.5] "V"  MBMU,PC

BO_ 2333671259 S2A_SUMDATA18__27: 8 SBMU
 SG_ S2A_BAT_I_HVS_27 : 0|16@1+ (0.1,-2000) [-2000|4553.5] "A"  MBMU,PC
 SG_ BAT_U_HVS_27 : 16|16@1+ (0.1,0) [0|6553.5] "V"  MBMU,PC
 SG_ BAT_U_TOT_HVS_27 : 32|16@1+ (0.1,0) [0|6553.5] "V"  MBMU,PC

BO_ 2333671260 S2A_SUMDATA18__28: 8 SBMU
 SG_ S2A_BAT_I_HVS_28 : 0|16@1+ (0.1,-2000) [-2000|4553.5] "A"  MBMU,PC
 SG_ BAT_U_HVS_28 : 16|16@1+ (0.1,0) [0|6553.5] "V"  MBMU,PC
 SG_ BAT_U_TOT_HVS_28 : 32|16@1+ (0.1,0) [0|6553.5] "V"  MBMU,PC

BO_ 2333671261 S2A_SUMDATA18__29: 8 SBMU
 SG_ S2A_BAT_I_HVS_29 : 0|16@1+ (0.1,-2000) [-2000|4553.5] "A"  MBMU,PC
 SG_ BAT_U_HVS_29 : 16|16@1+ (0.1,0) [0|6553.5] "V"  MBMU,PC
 SG_ BAT_U_TOT_HVS_29 : 32|16@1+ (0.1,0) [0|6553.5] "V"  MBMU,PC

BO_ 2333671262 S2A_SUMDATA18__30: 8 SBMU
 SG_ S2A_BAT_I_HVS_30 : 0|16@1+ (0.1,-2000) [-2000|4553.5] "A"  MBMU,PC
 SG_ BAT_U_HVS_30 : 16|16@1+ (0.1,0) [0|6553.5] "V"  MBMU,PC
 SG_ BAT_U_TOT_HVS_30 : 32|16@1+ (0.1,0) [0|6553.5] "V"  MBMU,PC

BO_ 2333671263 S2A_SUMDATA18__31: 8 SBMU
 SG_ S2A_BAT_I_HVS_31 : 0|16@1+ (0.1,-2000) [-2000|4553.5] "A"  MBMU,PC
 SG_ BAT_U_HVS_31 : 16|16@1+ (0.1,0) [0|6553.5] "V"  MBMU,PC
 SG_ BAT_U_TOT_HVS_31 : 32|16@1+ (0.1,0) [0|6553.5] "V"  MBMU,PC

BO_ 2333671264 S2A_SUMDATA18__32: 8 SBMU
 SG_ S2A_BAT_I_HVS_32 : 0|16@1+ (0.1,-2000) [-2000|4553.5] "A"  MBMU,PC
 SG_ BAT_U_HVS_32 : 16|16@1+ (0.1,0) [0|6553.5] "V"  MBMU,PC
 SG_ BAT_U_TOT_HVS_32 : 32|16@1+ (0.1,0) [0|6553.5] "V"  MBMU,PC

BO_ 2333671265 S2A_SUMDATA18__33: 8 SBMU
 SG_ S2A_BAT_I_HVS_33 : 0|16@1+ (0.1,-2000) [-2000|4553.5] "A"  MBMU,PC
 SG_ BAT_U_HVS_33 : 16|16@1+ (0.1,0) [0|6553.5] "V"  MBMU,PC
 SG_ BAT_U_TOT_HVS_33 : 32|16@1+ (0.1,0) [0|6553.5] "V"  MBMU,PC

BO_ 2333671266 S2A_SUMDATA18__34: 8 SBMU
 SG_ S2A_BAT_I_HVS_34 : 0|16@1+ (0.1,-2000) [-2000|4553.5] "A"  MBMU,PC
 SG_ BAT_U_HVS_34 : 16|16@1+ (0.1,0) [0|6553.5] "V"  MBMU,PC
 SG_ BAT_U_TOT_HVS_34 : 32|16@1+ (0.1,0) [0|6553.5] "V"  MBMU,PC

BO_ 2333671267 S2A_SUMDATA18__35: 8 SBMU
 SG_ S2A_BAT_I_HVS_35 : 0|16@1+ (0.1,-2000) [-2000|4553.5] "A"  MBMU,PC
 SG_ BAT_U_HVS_35 : 16|16@1+ (0.1,0) [0|6553.5] "V"  MBMU,PC
 SG_ BAT_U_TOT_HVS_35 : 32|16@1+ (0.1,0) [0|6553.5] "V"  MBMU,PC

BO_ 2333671268 S2A_SUMDATA18__36: 8 SBMU
 SG_ S2A_BAT_I_HVS_36 : 0|16@1+ (0.1,-2000) [-2000|4553.5] "A"  MBMU,PC
 SG_ BAT_U_HVS_36 : 16|16@1+ (0.1,0) [0|6553.5] "V"  MBMU,PC
 SG_ BAT_U_TOT_HVS_36 : 32|16@1+ (0.1,0) [0|6553.5] "V"  MBMU,PC

BO_ 2333671269 S2A_SUMDATA18__37: 8 SBMU
 SG_ S2A_BAT_I_HVS_37 : 0|16@1+ (0.1,-2000) [-2000|4553.5] "A"  MBMU,PC
 SG_ BAT_U_HVS_37 : 16|16@1+ (0.1,0) [0|6553.5] "V"  MBMU,PC
 SG_ BAT_U_TOT_HVS_37 : 32|16@1+ (0.1,0) [0|6553.5] "V"  MBMU,PC

BO_ 2333671270 S2A_SUMDATA18__38: 8 SBMU
 SG_ S2A_BAT_I_HVS_38 : 0|16@1+ (0.1,-2000) [-2000|4553.5] "A"  MBMU,PC
 SG_ BAT_U_HVS_38 : 16|16@1+ (0.1,0) [0|6553.5] "V"  MBMU,PC
 SG_ BAT_U_TOT_HVS_38 : 32|16@1+ (0.1,0) [0|6553.5] "V"  MBMU,PC

BO_ 2333671271 S2A_SUMDATA18__39: 8 SBMU
 SG_ S2A_BAT_I_HVS_39 : 0|16@1+ (0.1,-2000) [-2000|4553.5] "A"  MBMU,PC
 SG_ BAT_U_HVS_39 : 16|16@1+ (0.1,0) [0|6553.5] "V"  MBMU,PC
 SG_ BAT_U_TOT_HVS_39 : 32|16@1+ (0.1,0) [0|6553.5] "V"  MBMU,PC

BO_ 2333671272 S2A_SUMDATA18__40: 8 SBMU
 SG_ S2A_BAT_I_HVS_40 : 0|16@1+ (0.1,-2000) [-2000|4553.5] "A"  MBMU,PC
 SG_ BAT_U_HVS_40 : 16|16@1+ (0.1,0) [0|6553.5] "V"  MBMU,PC
 SG_ BAT_U_TOT_HVS_40 : 32|16@1+ (0.1,0) [0|6553.5] "V"  MBMU,PC

BO_ 2333671273 S2A_SUMDATA18__41: 8 SBMU
 SG_ S2A_BAT_I_HVS_41 : 0|16@1+ (0.1,-2000) [-2000|4553.5] "A"  MBMU,PC
 SG_ BAT_U_HVS_41 : 16|16@1+ (0.1,0) [0|6553.5] "V"  MBMU,PC
 SG_ BAT_U_TOT_HVS_41 : 32|16@1+ (0.1,0) [0|6553.5] "V"  MBMU,PC

BO_ 2333671274 S2A_SUMDATA18__42: 8 SBMU
 SG_ S2A_BAT_I_HVS_42 : 0|16@1+ (0.1,-2000) [-2000|4553.5] "A"  MBMU,PC
 SG_ BAT_U_HVS_42 : 16|16@1+ (0.1,0) [0|6553.5] "V"  MBMU,PC
 SG_ BAT_U_TOT_HVS_42 : 32|16@1+ (0.1,0) [0|6553.5] "V"  MBMU,PC

BO_ 2333671275 S2A_SUMDATA18__43: 8 SBMU
 SG_ S2A_BAT_I_HVS_43 : 0|16@1+ (0.1,-2000) [-2000|4553.5] "A"  MBMU,PC
 SG_ BAT_U_HVS_43 : 16|16@1+ (0.1,0) [0|6553.5] "V"  MBMU,PC
 SG_ BAT_U_TOT_HVS_43 : 32|16@1+ (0.1,0) [0|6553.5] "V"  MBMU,PC

BO_ 2333671276 S2A_SUMDATA18__44: 8 SBMU
 SG_ S2A_BAT_I_HVS_44 : 0|16@1+ (0.1,-2000) [-2000|4553.5] "A"  MBMU,PC
 SG_ BAT_U_HVS_44 : 16|16@1+ (0.1,0) [0|6553.5] "V"  MBMU,PC
 SG_ BAT_U_TOT_HVS_44 : 32|16@1+ (0.1,0) [0|6553.5] "V"  MBMU,PC

BO_ 2333671277 S2A_SUMDATA18__45: 8 SBMU
 SG_ S2A_BAT_I_HVS_45 : 0|16@1+ (0.1,-2000) [-2000|4553.5] "A"  MBMU,PC
 SG_ BAT_U_HVS_45 : 16|16@1+ (0.1,0) [0|6553.5] "V"  MBMU,PC
 SG_ BAT_U_TOT_HVS_45 : 32|16@1+ (0.1,0) [0|6553.5] "V"  MBMU,PC

BO_ 2333671278 S2A_SUMDATA18__46: 8 SBMU
 SG_ S2A_BAT_I_HVS_46 : 0|16@1+ (0.1,-2000) [-2000|4553.5] "A"  MBMU,PC
 SG_ BAT_U_HVS_46 : 16|16@1+ (0.1,0) [0|6553.5] "V"  MBMU,PC
 SG_ BAT_U_TOT_HVS_46 : 32|16@1+ (0.1,0) [0|6553.5] "V"  MBMU,PC

BO_ 2333671279 S2A_SUMDATA18__47: 8 SBMU
 SG_ S2A_BAT_I_HVS_47 : 0|16@1+ (0.1,-2000) [-2000|4553.5] "A"  MBMU,PC
 SG_ BAT_U_HVS_47 : 16|16@1+ (0.1,0) [0|6553.5] "V"  MBMU,PC
 SG_ BAT_U_TOT_HVS_47 : 32|16@1+ (0.1,0) [0|6553.5] "V"  MBMU,PC

BO_ 2333671280 S2A_SUMDATA18__48: 8 SBMU
 SG_ S2A_BAT_I_HVS_48 : 0|16@1+ (0.1,-2000) [-2000|4553.5] "A"  MBMU,PC
 SG_ BAT_U_HVS_48 : 16|16@1+ (0.1,0) [0|6553.5] "V"  MBMU,PC
 SG_ BAT_U_TOT_HVS_48 : 32|16@1+ (0.1,0) [0|6553.5] "V"  MBMU,PC

BO_ 2333671281 S2A_SUMDATA18__49: 8 SBMU
 SG_ S2A_BAT_I_HVS_49 : 0|16@1+ (0.1,-2000) [-2000|4553.5] "A"  MBMU,PC
 SG_ BAT_U_HVS_49 : 16|16@1+ (0.1,0) [0|6553.5] "V"  MBMU,PC
 SG_ BAT_U_TOT_HVS_49 : 32|16@1+ (0.1,0) [0|6553.5] "V"  MBMU,PC

BO_ 2333671282 S2A_SUMDATA18__50: 8 SBMU
 SG_ S2A_BAT_I_HVS_50 : 0|16@1+ (0.1,-2000) [-2000|4553.5] "A"  MBMU,PC
 SG_ BAT_U_HVS_50 : 16|16@1+ (0.1,0) [0|6553.5] "V"  MBMU,PC
 SG_ BAT_U_TOT_HVS_50 : 32|16@1+ (0.1,0) [0|6553.5] "V"  MBMU,PC

BO_ 2333671283 S2A_SUMDATA18__51: 8 SBMU
 SG_ S2A_BAT_I_HVS_51 : 0|16@1+ (0.1,-2000) [-2000|4553.5] "A"  MBMU,PC
 SG_ BAT_U_HVS_51 : 16|16@1+ (0.1,0) [0|6553.5] "V"  MBMU,PC
 SG_ BAT_U_TOT_HVS_51 : 32|16@1+ (0.1,0) [0|6553.5] "V"  MBMU,PC

BO_ 2333671284 S2A_SUMDATA18__52: 8 SBMU
 SG_ S2A_BAT_I_HVS_52 : 0|16@1+ (0.1,-2000) [-2000|4553.5] "A"  MBMU,PC
 SG_ BAT_U_HVS_52 : 16|16@1+ (0.1,0) [0|6553.5] "V"  MBMU,PC
 SG_ BAT_U_TOT_HVS_52 : 32|16@1+ (0.1,0) [0|6553.5] "V"  MBMU,PC

BO_ 2333671285 S2A_SUMDATA18__53: 8 SBMU
 SG_ S2A_BAT_I_HVS_53 : 0|16@1+ (0.1,-2000) [-2000|4553.5] "A"  MBMU,PC
 SG_ BAT_U_HVS_53 : 16|16@1+ (0.1,0) [0|6553.5] "V"  MBMU,PC
 SG_ BAT_U_TOT_HVS_53 : 32|16@1+ (0.1,0) [0|6553.5] "V"  MBMU,PC

BO_ 2333671286 S2A_SUMDATA18__54: 8 SBMU
 SG_ S2A_BAT_I_HVS_54 : 0|16@1+ (0.1,-2000) [-2000|4553.5] "A"  MBMU,PC
 SG_ BAT_U_HVS_54 : 16|16@1+ (0.1,0) [0|6553.5] "V"  MBMU,PC
 SG_ BAT_U_TOT_HVS_54 : 32|16@1+ (0.1,0) [0|6553.5] "V"  MBMU,PC

BO_ 2333671287 S2A_SUMDATA18__55: 8 SBMU
 SG_ S2A_BAT_I_HVS_55 : 0|16@1+ (0.1,-2000) [-2000|4553.5] "A"  MBMU,PC
 SG_ BAT_U_HVS_55 : 16|16@1+ (0.1,0) [0|6553.5] "V"  MBMU,PC
 SG_ BAT_U_TOT_HVS_55 : 32|16@1+ (0.1,0) [0|6553.5] "V"  MBMU,PC

BO_ 2333671288 S2A_SUMDATA18__56: 8 SBMU
 SG_ S2A_BAT_I_HVS_56 : 0|16@1+ (0.1,-2000) [-2000|4553.5] "A"  MBMU,PC
 SG_ BAT_U_HVS_56 : 16|16@1+ (0.1,0) [0|6553.5] "V"  MBMU,PC
 SG_ BAT_U_TOT_HVS_56 : 32|16@1+ (0.1,0) [0|6553.5] "V"  MBMU,PC

BO_ 2333671289 S2A_SUMDATA18__57: 8 SBMU
 SG_ S2A_BAT_I_HVS_57 : 0|16@1+ (0.1,-2000) [-2000|4553.5] "A"  MBMU,PC
 SG_ BAT_U_HVS_57 : 16|16@1+ (0.1,0) [0|6553.5] "V"  MBMU,PC
 SG_ BAT_U_TOT_HVS_57 : 32|16@1+ (0.1,0) [0|6553.5] "V"  MBMU,PC

BO_ 2333671290 S2A_SUMDATA18__58: 8 SBMU
 SG_ S2A_BAT_I_HVS_58 : 0|16@1+ (0.1,-2000) [-2000|4553.5] "A"  MBMU,PC
 SG_ BAT_U_HVS_58 : 16|16@1+ (0.1,0) [0|6553.5] "V"  MBMU,PC
 SG_ BAT_U_TOT_HVS_58 : 32|16@1+ (0.1,0) [0|6553.5] "V"  MBMU,PC

BO_ 2333671291 S2A_SUMDATA18__59: 8 SBMU
 SG_ S2A_BAT_I_HVS_59 : 0|16@1+ (0.1,-2000) [-2000|4553.5] "A"  MBMU,PC
 SG_ BAT_U_HVS_59 : 16|16@1+ (0.1,0) [0|6553.5] "V"  MBMU,PC
 SG_ BAT_U_TOT_HVS_59 : 32|16@1+ (0.1,0) [0|6553.5] "V"  MBMU,PC

BO_ 2333671292 S2A_SUMDATA18__60: 8 SBMU
 SG_ S2A_BAT_I_HVS_60 : 0|16@1+ (0.1,-2000) [-2000|4553.5] "A"  MBMU,PC
 SG_ BAT_U_HVS_60 : 16|16@1+ (0.1,0) [0|6553.5] "V"  MBMU,PC
 SG_ BAT_U_TOT_HVS_60 : 32|16@1+ (0.1,0) [0|6553.5] "V"  MBMU,PC

BO_ 2333671293 S2A_SUMDATA18__61: 8 SBMU
 SG_ S2A_BAT_I_HVS_61 : 0|16@1+ (0.1,-2000) [-2000|4553.5] "A"  MBMU,PC
 SG_ BAT_U_HVS_61 : 16|16@1+ (0.1,0) [0|6553.5] "V"  MBMU,PC
 SG_ BAT_U_TOT_HVS_61 : 32|16@1+ (0.1,0) [0|6553.5] "V"  MBMU,PC

BO_ 2333671294 S2A_SUMDATA18__62: 8 SBMU
 SG_ S2A_BAT_I_HVS_62 : 0|16@1+ (0.1,-2000) [-2000|4553.5] "A"  MBMU,PC
 SG_ BAT_U_HVS_62 : 16|16@1+ (0.1,0) [0|6553.5] "V"  MBMU,PC
 SG_ BAT_U_TOT_HVS_62 : 32|16@1+ (0.1,0) [0|6553.5] "V"  MBMU,PC

BO_ 2333671295 S2A_SUMDATA18__63: 8 SBMU
 SG_ S2A_BAT_I_HVS_63 : 0|16@1+ (0.1,-2000) [-2000|4553.5] "A"  MBMU,PC
 SG_ BAT_U_HVS_63 : 16|16@1+ (0.1,0) [0|6553.5] "V"  MBMU,PC
 SG_ BAT_U_TOT_HVS_63 : 32|16@1+ (0.1,0) [0|6553.5] "V"  MBMU,PC

BO_ 2400644673 S2P_Detail_Tpole__01: 8 SBMU
 SG_ CSC_Tpole_No_01 : 0|8@1+ (1,0) [0|255] ""  PC
 SG_ CSC_Tpole_Frame_Index_01 M : 8|8@1+ (1,0) [0|255] ""  PC
 SG_ CSC_Tpole_01_01 m0 : 16|8@1+ (1,-50) [-50|205] "℃"  PC
 SG_ CSC_Tpole_02_01 m0 : 24|8@1+ (1,-50) [-50|205] "℃"  PC
 SG_ CSC_Tpole_03_01 m0 : 32|8@1+ (1,-50) [-50|205] "℃"  PC
 SG_ CSC_Tpole_04_01 m0 : 40|8@1+ (1,-50) [-50|205] "℃"  PC
 SG_ CSC_Tpole_05_01 m0 : 48|8@1+ (1,-50) [-50|205] "℃"  PC
 SG_ CSC_Tpole_06_01 m0 : 56|8@1+ (1,-50) [-50|205] "℃"  PC

BO_ 2400644674 S2P_Detail_Tpole__02: 8 SBMU
 SG_ CSC_Tpole_No_02 : 0|8@1+ (1,0) [0|255] ""  PC
 SG_ CSC_Tpole_Frame_Index_02 M : 8|8@1+ (1,0) [0|255] ""  PC
 SG_ CSC_Tpole_01_02 m0 : 16|8@1+ (1,-50) [-50|205] "℃"  PC
 SG_ CSC_Tpole_02_02 m0 : 24|8@1+ (1,-50) [-50|205] "℃"  PC
 SG_ CSC_Tpole_03_02 m0 : 32|8@1+ (1,-50) [-50|205] "℃"  PC
 SG_ CSC_Tpole_04_02 m0 : 40|8@1+ (1,-50) [-50|205] "℃"  PC
 SG_ CSC_Tpole_05_02 m0 : 48|8@1+ (1,-50) [-50|205] "℃"  PC
 SG_ CSC_Tpole_06_02 m0 : 56|8@1+ (1,-50) [-50|205] "℃"  PC

BO_ 2400644675 S2P_Detail_Tpole__03: 8 SBMU
 SG_ CSC_Tpole_No_03 : 0|8@1+ (1,0) [0|255] ""  PC
 SG_ CSC_Tpole_Frame_Index_03 M : 8|8@1+ (1,0) [0|255] ""  PC
 SG_ CSC_Tpole_01_03 m0 : 16|8@1+ (1,-50) [-50|205] "℃"  PC
 SG_ CSC_Tpole_02_03 m0 : 24|8@1+ (1,-50) [-50|205] "℃"  PC
 SG_ CSC_Tpole_03_03 m0 : 32|8@1+ (1,-50) [-50|205] "℃"  PC
 SG_ CSC_Tpole_04_03 m0 : 40|8@1+ (1,-50) [-50|205] "℃"  PC
 SG_ CSC_Tpole_05_03 m0 : 48|8@1+ (1,-50) [-50|205] "℃"  PC
 SG_ CSC_Tpole_06_03 m0 : 56|8@1+ (1,-50) [-50|205] "℃"  PC

BO_ 2400644676 S2P_Detail_Tpole__04: 8 SBMU
 SG_ CSC_Tpole_No_04 : 0|8@1+ (1,0) [0|255] ""  PC
 SG_ CSC_Tpole_Frame_Index_04 M : 8|8@1+ (1,0) [0|255] ""  PC
 SG_ CSC_Tpole_01_04 m0 : 16|8@1+ (1,-50) [-50|205] "℃"  PC
 SG_ CSC_Tpole_02_04 m0 : 24|8@1+ (1,-50) [-50|205] "℃"  PC
 SG_ CSC_Tpole_03_04 m0 : 32|8@1+ (1,-50) [-50|205] "℃"  PC
 SG_ CSC_Tpole_04_04 m0 : 40|8@1+ (1,-50) [-50|205] "℃"  PC
 SG_ CSC_Tpole_05_04 m0 : 48|8@1+ (1,-50) [-50|205] "℃"  PC
 SG_ CSC_Tpole_06_04 m0 : 56|8@1+ (1,-50) [-50|205] "℃"  PC

BO_ 2400644677 S2P_Detail_Tpole__05: 8 SBMU
 SG_ CSC_Tpole_No_05 : 0|8@1+ (1,0) [0|255] ""  PC
 SG_ CSC_Tpole_Frame_Index_05 M : 8|8@1+ (1,0) [0|255] ""  PC
 SG_ CSC_Tpole_01_05 m0 : 16|8@1+ (1,-50) [-50|205] "℃"  PC
 SG_ CSC_Tpole_02_05 m0 : 24|8@1+ (1,-50) [-50|205] "℃"  PC
 SG_ CSC_Tpole_03_05 m0 : 32|8@1+ (1,-50) [-50|205] "℃"  PC
 SG_ CSC_Tpole_04_05 m0 : 40|8@1+ (1,-50) [-50|205] "℃"  PC
 SG_ CSC_Tpole_05_05 m0 : 48|8@1+ (1,-50) [-50|205] "℃"  PC
 SG_ CSC_Tpole_06_05 m0 : 56|8@1+ (1,-50) [-50|205] "℃"  PC

BO_ 2400644678 S2P_Detail_Tpole__06: 8 SBMU
 SG_ CSC_Tpole_No_06 : 0|8@1+ (1,0) [0|255] ""  PC
 SG_ CSC_Tpole_Frame_Index_06 M : 8|8@1+ (1,0) [0|255] ""  PC
 SG_ CSC_Tpole_01_06 m0 : 16|8@1+ (1,-50) [-50|205] "℃"  PC
 SG_ CSC_Tpole_02_06 m0 : 24|8@1+ (1,-50) [-50|205] "℃"  PC
 SG_ CSC_Tpole_03_06 m0 : 32|8@1+ (1,-50) [-50|205] "℃"  PC
 SG_ CSC_Tpole_04_06 m0 : 40|8@1+ (1,-50) [-50|205] "℃"  PC
 SG_ CSC_Tpole_05_06 m0 : 48|8@1+ (1,-50) [-50|205] "℃"  PC
 SG_ CSC_Tpole_06_06 m0 : 56|8@1+ (1,-50) [-50|205] "℃"  PC

BO_ 2400644679 S2P_Detail_Tpole__07: 8 SBMU
 SG_ CSC_Tpole_No_07 : 0|8@1+ (1,0) [0|255] ""  PC
 SG_ CSC_Tpole_Frame_Index_07 M : 8|8@1+ (1,0) [0|255] ""  PC
 SG_ CSC_Tpole_01_07 m0 : 16|8@1+ (1,-50) [-50|205] "℃"  PC
 SG_ CSC_Tpole_02_07 m0 : 24|8@1+ (1,-50) [-50|205] "℃"  PC
 SG_ CSC_Tpole_03_07 m0 : 32|8@1+ (1,-50) [-50|205] "℃"  PC
 SG_ CSC_Tpole_04_07 m0 : 40|8@1+ (1,-50) [-50|205] "℃"  PC
 SG_ CSC_Tpole_05_07 m0 : 48|8@1+ (1,-50) [-50|205] "℃"  PC
 SG_ CSC_Tpole_06_07 m0 : 56|8@1+ (1,-50) [-50|205] "℃"  PC

BO_ 2400644680 S2P_Detail_Tpole__08: 8 SBMU
 SG_ CSC_Tpole_No_08 : 0|8@1+ (1,0) [0|255] ""  PC
 SG_ CSC_Tpole_Frame_Index_08 M : 8|8@1+ (1,0) [0|255] ""  PC
 SG_ CSC_Tpole_01_08 m0 : 16|8@1+ (1,-50) [-50|205] "℃"  PC
 SG_ CSC_Tpole_02_08 m0 : 24|8@1+ (1,-50) [-50|205] "℃"  PC
 SG_ CSC_Tpole_03_08 m0 : 32|8@1+ (1,-50) [-50|205] "℃"  PC
 SG_ CSC_Tpole_04_08 m0 : 40|8@1+ (1,-50) [-50|205] "℃"  PC
 SG_ CSC_Tpole_05_08 m0 : 48|8@1+ (1,-50) [-50|205] "℃"  PC
 SG_ CSC_Tpole_06_08 m0 : 56|8@1+ (1,-50) [-50|205] "℃"  PC

BO_ 2400644681 S2P_Detail_Tpole__09: 8 SBMU
 SG_ CSC_Tpole_No_09 : 0|8@1+ (1,0) [0|255] ""  PC
 SG_ CSC_Tpole_Frame_Index_09 M : 8|8@1+ (1,0) [0|255] ""  PC
 SG_ CSC_Tpole_01_09 m0 : 16|8@1+ (1,-50) [-50|205] "℃"  PC
 SG_ CSC_Tpole_02_09 m0 : 24|8@1+ (1,-50) [-50|205] "℃"  PC
 SG_ CSC_Tpole_03_09 m0 : 32|8@1+ (1,-50) [-50|205] "℃"  PC
 SG_ CSC_Tpole_04_09 m0 : 40|8@1+ (1,-50) [-50|205] "℃"  PC
 SG_ CSC_Tpole_05_09 m0 : 48|8@1+ (1,-50) [-50|205] "℃"  PC
 SG_ CSC_Tpole_06_09 m0 : 56|8@1+ (1,-50) [-50|205] "℃"  PC

BO_ 2400644682 S2P_Detail_Tpole__10: 8 SBMU
 SG_ CSC_Tpole_No_10 : 0|8@1+ (1,0) [0|255] ""  PC
 SG_ CSC_Tpole_Frame_Index_10 M : 8|8@1+ (1,0) [0|255] ""  PC
 SG_ CSC_Tpole_01_10 m0 : 16|8@1+ (1,-50) [-50|205] "℃"  PC
 SG_ CSC_Tpole_02_10 m0 : 24|8@1+ (1,-50) [-50|205] "℃"  PC
 SG_ CSC_Tpole_03_10 m0 : 32|8@1+ (1,-50) [-50|205] "℃"  PC
 SG_ CSC_Tpole_04_10 m0 : 40|8@1+ (1,-50) [-50|205] "℃"  PC
 SG_ CSC_Tpole_05_10 m0 : 48|8@1+ (1,-50) [-50|205] "℃"  PC
 SG_ CSC_Tpole_06_10 m0 : 56|8@1+ (1,-50) [-50|205] "℃"  PC

BO_ 2400644683 S2P_Detail_Tpole__11: 8 SBMU
 SG_ CSC_Tpole_No_11 : 0|8@1+ (1,0) [0|255] ""  PC
 SG_ CSC_Tpole_Frame_Index_11 M : 8|8@1+ (1,0) [0|255] ""  PC
 SG_ CSC_Tpole_01_11 m0 : 16|8@1+ (1,-50) [-50|205] "℃"  PC
 SG_ CSC_Tpole_02_11 m0 : 24|8@1+ (1,-50) [-50|205] "℃"  PC
 SG_ CSC_Tpole_03_11 m0 : 32|8@1+ (1,-50) [-50|205] "℃"  PC
 SG_ CSC_Tpole_04_11 m0 : 40|8@1+ (1,-50) [-50|205] "℃"  PC
 SG_ CSC_Tpole_05_11 m0 : 48|8@1+ (1,-50) [-50|205] "℃"  PC
 SG_ CSC_Tpole_06_11 m0 : 56|8@1+ (1,-50) [-50|205] "℃"  PC

BO_ 2400644684 S2P_Detail_Tpole__12: 8 SBMU
 SG_ CSC_Tpole_No_12 : 0|8@1+ (1,0) [0|255] ""  PC
 SG_ CSC_Tpole_Frame_Index_12 M : 8|8@1+ (1,0) [0|255] ""  PC
 SG_ CSC_Tpole_01_12 m0 : 16|8@1+ (1,-50) [-50|205] "℃"  PC
 SG_ CSC_Tpole_02_12 m0 : 24|8@1+ (1,-50) [-50|205] "℃"  PC
 SG_ CSC_Tpole_03_12 m0 : 32|8@1+ (1,-50) [-50|205] "℃"  PC
 SG_ CSC_Tpole_04_12 m0 : 40|8@1+ (1,-50) [-50|205] "℃"  PC
 SG_ CSC_Tpole_05_12 m0 : 48|8@1+ (1,-50) [-50|205] "℃"  PC
 SG_ CSC_Tpole_06_12 m0 : 56|8@1+ (1,-50) [-50|205] "℃"  PC

BO_ 2400644685 S2P_Detail_Tpole__13: 8 SBMU
 SG_ CSC_Tpole_No_13 : 0|8@1+ (1,0) [0|255] ""  PC
 SG_ CSC_Tpole_Frame_Index_13 M : 8|8@1+ (1,0) [0|255] ""  PC
 SG_ CSC_Tpole_01_13 m0 : 16|8@1+ (1,-50) [-50|205] "℃"  PC
 SG_ CSC_Tpole_02_13 m0 : 24|8@1+ (1,-50) [-50|205] "℃"  PC
 SG_ CSC_Tpole_03_13 m0 : 32|8@1+ (1,-50) [-50|205] "℃"  PC
 SG_ CSC_Tpole_04_13 m0 : 40|8@1+ (1,-50) [-50|205] "℃"  PC
 SG_ CSC_Tpole_05_13 m0 : 48|8@1+ (1,-50) [-50|205] "℃"  PC
 SG_ CSC_Tpole_06_13 m0 : 56|8@1+ (1,-50) [-50|205] "℃"  PC

BO_ 2400644686 S2P_Detail_Tpole__14: 8 SBMU
 SG_ CSC_Tpole_No_14 : 0|8@1+ (1,0) [0|255] ""  PC
 SG_ CSC_Tpole_Frame_Index_14 M : 8|8@1+ (1,0) [0|255] ""  PC
 SG_ CSC_Tpole_01_14 m0 : 16|8@1+ (1,-50) [-50|205] "℃"  PC
 SG_ CSC_Tpole_02_14 m0 : 24|8@1+ (1,-50) [-50|205] "℃"  PC
 SG_ CSC_Tpole_03_14 m0 : 32|8@1+ (1,-50) [-50|205] "℃"  PC
 SG_ CSC_Tpole_04_14 m0 : 40|8@1+ (1,-50) [-50|205] "℃"  PC
 SG_ CSC_Tpole_05_14 m0 : 48|8@1+ (1,-50) [-50|205] "℃"  PC
 SG_ CSC_Tpole_06_14 m0 : 56|8@1+ (1,-50) [-50|205] "℃"  PC

BO_ 2400644687 S2P_Detail_Tpole__15: 8 SBMU
 SG_ CSC_Tpole_No_15 : 0|8@1+ (1,0) [0|255] ""  PC
 SG_ CSC_Tpole_Frame_Index_15 M : 8|8@1+ (1,0) [0|255] ""  PC
 SG_ CSC_Tpole_01_15 m0 : 16|8@1+ (1,-50) [-50|205] "℃"  PC
 SG_ CSC_Tpole_02_15 m0 : 24|8@1+ (1,-50) [-50|205] "℃"  PC
 SG_ CSC_Tpole_03_15 m0 : 32|8@1+ (1,-50) [-50|205] "℃"  PC
 SG_ CSC_Tpole_04_15 m0 : 40|8@1+ (1,-50) [-50|205] "℃"  PC
 SG_ CSC_Tpole_05_15 m0 : 48|8@1+ (1,-50) [-50|205] "℃"  PC
 SG_ CSC_Tpole_06_15 m0 : 56|8@1+ (1,-50) [-50|205] "℃"  PC

BO_ 2400644688 S2P_Detail_Tpole__16: 8 SBMU
 SG_ CSC_Tpole_No_16 : 0|8@1+ (1,0) [0|255] ""  PC
 SG_ CSC_Tpole_Frame_Index_16 M : 8|8@1+ (1,0) [0|255] ""  PC
 SG_ CSC_Tpole_01_16 m0 : 16|8@1+ (1,-50) [-50|205] "℃"  PC
 SG_ CSC_Tpole_02_16 m0 : 24|8@1+ (1,-50) [-50|205] "℃"  PC
 SG_ CSC_Tpole_03_16 m0 : 32|8@1+ (1,-50) [-50|205] "℃"  PC
 SG_ CSC_Tpole_04_16 m0 : 40|8@1+ (1,-50) [-50|205] "℃"  PC
 SG_ CSC_Tpole_05_16 m0 : 48|8@1+ (1,-50) [-50|205] "℃"  PC
 SG_ CSC_Tpole_06_16 m0 : 56|8@1+ (1,-50) [-50|205] "℃"  PC

BO_ 2400644689 S2P_Detail_Tpole__17: 8 SBMU
 SG_ CSC_Tpole_No_17 : 0|8@1+ (1,0) [0|255] ""  PC
 SG_ CSC_Tpole_Frame_Index_17 M : 8|8@1+ (1,0) [0|255] ""  PC
 SG_ CSC_Tpole_01_17 m0 : 16|8@1+ (1,-50) [-50|205] "℃"  PC
 SG_ CSC_Tpole_02_17 m0 : 24|8@1+ (1,-50) [-50|205] "℃"  PC
 SG_ CSC_Tpole_03_17 m0 : 32|8@1+ (1,-50) [-50|205] "℃"  PC
 SG_ CSC_Tpole_04_17 m0 : 40|8@1+ (1,-50) [-50|205] "℃"  PC
 SG_ CSC_Tpole_05_17 m0 : 48|8@1+ (1,-50) [-50|205] "℃"  PC
 SG_ CSC_Tpole_06_17 m0 : 56|8@1+ (1,-50) [-50|205] "℃"  PC

BO_ 2400644690 S2P_Detail_Tpole__18: 8 SBMU
 SG_ CSC_Tpole_No_18 : 0|8@1+ (1,0) [0|255] ""  PC
 SG_ CSC_Tpole_Frame_Index_18 M : 8|8@1+ (1,0) [0|255] ""  PC
 SG_ CSC_Tpole_01_18 m0 : 16|8@1+ (1,-50) [-50|205] "℃"  PC
 SG_ CSC_Tpole_02_18 m0 : 24|8@1+ (1,-50) [-50|205] "℃"  PC
 SG_ CSC_Tpole_03_18 m0 : 32|8@1+ (1,-50) [-50|205] "℃"  PC
 SG_ CSC_Tpole_04_18 m0 : 40|8@1+ (1,-50) [-50|205] "℃"  PC
 SG_ CSC_Tpole_05_18 m0 : 48|8@1+ (1,-50) [-50|205] "℃"  PC
 SG_ CSC_Tpole_06_18 m0 : 56|8@1+ (1,-50) [-50|205] "℃"  PC

BO_ 2400644691 S2P_Detail_Tpole__19: 8 SBMU
 SG_ CSC_Tpole_No_19 : 0|8@1+ (1,0) [0|255] ""  PC
 SG_ CSC_Tpole_Frame_Index_19 M : 8|8@1+ (1,0) [0|255] ""  PC
 SG_ CSC_Tpole_01_19 m0 : 16|8@1+ (1,-50) [-50|205] "℃"  PC
 SG_ CSC_Tpole_02_19 m0 : 24|8@1+ (1,-50) [-50|205] "℃"  PC
 SG_ CSC_Tpole_03_19 m0 : 32|8@1+ (1,-50) [-50|205] "℃"  PC
 SG_ CSC_Tpole_04_19 m0 : 40|8@1+ (1,-50) [-50|205] "℃"  PC
 SG_ CSC_Tpole_05_19 m0 : 48|8@1+ (1,-50) [-50|205] "℃"  PC
 SG_ CSC_Tpole_06_19 m0 : 56|8@1+ (1,-50) [-50|205] "℃"  PC

BO_ 2400644692 S2P_Detail_Tpole__20: 8 SBMU
 SG_ CSC_Tpole_No_20 : 0|8@1+ (1,0) [0|255] ""  PC
 SG_ CSC_Tpole_Frame_Index_20 M : 8|8@1+ (1,0) [0|255] ""  PC
 SG_ CSC_Tpole_01_20 m0 : 16|8@1+ (1,-50) [-50|205] "℃"  PC
 SG_ CSC_Tpole_02_20 m0 : 24|8@1+ (1,-50) [-50|205] "℃"  PC
 SG_ CSC_Tpole_03_20 m0 : 32|8@1+ (1,-50) [-50|205] "℃"  PC
 SG_ CSC_Tpole_04_20 m0 : 40|8@1+ (1,-50) [-50|205] "℃"  PC
 SG_ CSC_Tpole_05_20 m0 : 48|8@1+ (1,-50) [-50|205] "℃"  PC
 SG_ CSC_Tpole_06_20 m0 : 56|8@1+ (1,-50) [-50|205] "℃"  PC

BO_ 2400644693 S2P_Detail_Tpole__21: 8 SBMU
 SG_ CSC_Tpole_No_21 : 0|8@1+ (1,0) [0|255] ""  PC
 SG_ CSC_Tpole_Frame_Index_21 M : 8|8@1+ (1,0) [0|255] ""  PC
 SG_ CSC_Tpole_01_21 m0 : 16|8@1+ (1,-50) [-50|205] "℃"  PC
 SG_ CSC_Tpole_02_21 m0 : 24|8@1+ (1,-50) [-50|205] "℃"  PC
 SG_ CSC_Tpole_03_21 m0 : 32|8@1+ (1,-50) [-50|205] "℃"  PC
 SG_ CSC_Tpole_04_21 m0 : 40|8@1+ (1,-50) [-50|205] "℃"  PC
 SG_ CSC_Tpole_05_21 m0 : 48|8@1+ (1,-50) [-50|205] "℃"  PC
 SG_ CSC_Tpole_06_21 m0 : 56|8@1+ (1,-50) [-50|205] "℃"  PC

BO_ 2400644694 S2P_Detail_Tpole__22: 8 SBMU
 SG_ CSC_Tpole_No_22 : 0|8@1+ (1,0) [0|255] ""  PC
 SG_ CSC_Tpole_Frame_Index_22 M : 8|8@1+ (1,0) [0|255] ""  PC
 SG_ CSC_Tpole_01_22 m0 : 16|8@1+ (1,-50) [-50|205] "℃"  PC
 SG_ CSC_Tpole_02_22 m0 : 24|8@1+ (1,-50) [-50|205] "℃"  PC
 SG_ CSC_Tpole_03_22 m0 : 32|8@1+ (1,-50) [-50|205] "℃"  PC
 SG_ CSC_Tpole_04_22 m0 : 40|8@1+ (1,-50) [-50|205] "℃"  PC
 SG_ CSC_Tpole_05_22 m0 : 48|8@1+ (1,-50) [-50|205] "℃"  PC
 SG_ CSC_Tpole_06_22 m0 : 56|8@1+ (1,-50) [-50|205] "℃"  PC

BO_ 2400644695 S2P_Detail_Tpole__23: 8 SBMU
 SG_ CSC_Tpole_No_23 : 0|8@1+ (1,0) [0|255] ""  PC
 SG_ CSC_Tpole_Frame_Index_23 M : 8|8@1+ (1,0) [0|255] ""  PC
 SG_ CSC_Tpole_01_23 m0 : 16|8@1+ (1,-50) [-50|205] "℃"  PC
 SG_ CSC_Tpole_02_23 m0 : 24|8@1+ (1,-50) [-50|205] "℃"  PC
 SG_ CSC_Tpole_03_23 m0 : 32|8@1+ (1,-50) [-50|205] "℃"  PC
 SG_ CSC_Tpole_04_23 m0 : 40|8@1+ (1,-50) [-50|205] "℃"  PC
 SG_ CSC_Tpole_05_23 m0 : 48|8@1+ (1,-50) [-50|205] "℃"  PC
 SG_ CSC_Tpole_06_23 m0 : 56|8@1+ (1,-50) [-50|205] "℃"  PC

BO_ 2400644696 S2P_Detail_Tpole__24: 8 SBMU
 SG_ CSC_Tpole_No_24 : 0|8@1+ (1,0) [0|255] ""  PC
 SG_ CSC_Tpole_Frame_Index_24 M : 8|8@1+ (1,0) [0|255] ""  PC
 SG_ CSC_Tpole_01_24 m0 : 16|8@1+ (1,-50) [-50|205] "℃"  PC
 SG_ CSC_Tpole_02_24 m0 : 24|8@1+ (1,-50) [-50|205] "℃"  PC
 SG_ CSC_Tpole_03_24 m0 : 32|8@1+ (1,-50) [-50|205] "℃"  PC
 SG_ CSC_Tpole_04_24 m0 : 40|8@1+ (1,-50) [-50|205] "℃"  PC
 SG_ CSC_Tpole_05_24 m0 : 48|8@1+ (1,-50) [-50|205] "℃"  PC
 SG_ CSC_Tpole_06_24 m0 : 56|8@1+ (1,-50) [-50|205] "℃"  PC

BO_ 2400644697 S2P_Detail_Tpole__25: 8 SBMU
 SG_ CSC_Tpole_No_25 : 0|8@1+ (1,0) [0|255] ""  PC
 SG_ CSC_Tpole_Frame_Index_25 M : 8|8@1+ (1,0) [0|255] ""  PC
 SG_ CSC_Tpole_01_25 m0 : 16|8@1+ (1,-50) [-50|205] "℃"  PC
 SG_ CSC_Tpole_02_25 m0 : 24|8@1+ (1,-50) [-50|205] "℃"  PC
 SG_ CSC_Tpole_03_25 m0 : 32|8@1+ (1,-50) [-50|205] "℃"  PC
 SG_ CSC_Tpole_04_25 m0 : 40|8@1+ (1,-50) [-50|205] "℃"  PC
 SG_ CSC_Tpole_05_25 m0 : 48|8@1+ (1,-50) [-50|205] "℃"  PC
 SG_ CSC_Tpole_06_25 m0 : 56|8@1+ (1,-50) [-50|205] "℃"  PC

BO_ 2400644698 S2P_Detail_Tpole__26: 8 SBMU
 SG_ CSC_Tpole_No_26 : 0|8@1+ (1,0) [0|255] ""  PC
 SG_ CSC_Tpole_Frame_Index_26 M : 8|8@1+ (1,0) [0|255] ""  PC
 SG_ CSC_Tpole_01_26 m0 : 16|8@1+ (1,-50) [-50|205] "℃"  PC
 SG_ CSC_Tpole_02_26 m0 : 24|8@1+ (1,-50) [-50|205] "℃"  PC
 SG_ CSC_Tpole_03_26 m0 : 32|8@1+ (1,-50) [-50|205] "℃"  PC
 SG_ CSC_Tpole_04_26 m0 : 40|8@1+ (1,-50) [-50|205] "℃"  PC
 SG_ CSC_Tpole_05_26 m0 : 48|8@1+ (1,-50) [-50|205] "℃"  PC
 SG_ CSC_Tpole_06_26 m0 : 56|8@1+ (1,-50) [-50|205] "℃"  PC

BO_ 2400644699 S2P_Detail_Tpole__27: 8 SBMU
 SG_ CSC_Tpole_No_27 : 0|8@1+ (1,0) [0|255] ""  PC
 SG_ CSC_Tpole_Frame_Index_27 M : 8|8@1+ (1,0) [0|255] ""  PC
 SG_ CSC_Tpole_01_27 m0 : 16|8@1+ (1,-50) [-50|205] "℃"  PC
 SG_ CSC_Tpole_02_27 m0 : 24|8@1+ (1,-50) [-50|205] "℃"  PC
 SG_ CSC_Tpole_03_27 m0 : 32|8@1+ (1,-50) [-50|205] "℃"  PC
 SG_ CSC_Tpole_04_27 m0 : 40|8@1+ (1,-50) [-50|205] "℃"  PC
 SG_ CSC_Tpole_05_27 m0 : 48|8@1+ (1,-50) [-50|205] "℃"  PC
 SG_ CSC_Tpole_06_27 m0 : 56|8@1+ (1,-50) [-50|205] "℃"  PC

BO_ 2400644700 S2P_Detail_Tpole__28: 8 SBMU
 SG_ CSC_Tpole_No_28 : 0|8@1+ (1,0) [0|255] ""  PC
 SG_ CSC_Tpole_Frame_Index_28 M : 8|8@1+ (1,0) [0|255] ""  PC
 SG_ CSC_Tpole_01_28 m0 : 16|8@1+ (1,-50) [-50|205] "℃"  PC
 SG_ CSC_Tpole_02_28 m0 : 24|8@1+ (1,-50) [-50|205] "℃"  PC
 SG_ CSC_Tpole_03_28 m0 : 32|8@1+ (1,-50) [-50|205] "℃"  PC
 SG_ CSC_Tpole_04_28 m0 : 40|8@1+ (1,-50) [-50|205] "℃"  PC
 SG_ CSC_Tpole_05_28 m0 : 48|8@1+ (1,-50) [-50|205] "℃"  PC
 SG_ CSC_Tpole_06_28 m0 : 56|8@1+ (1,-50) [-50|205] "℃"  PC

BO_ 2400644701 S2P_Detail_Tpole__29: 8 SBMU
 SG_ CSC_Tpole_No_29 : 0|8@1+ (1,0) [0|255] ""  PC
 SG_ CSC_Tpole_Frame_Index_29 M : 8|8@1+ (1,0) [0|255] ""  PC
 SG_ CSC_Tpole_01_29 m0 : 16|8@1+ (1,-50) [-50|205] "℃"  PC
 SG_ CSC_Tpole_02_29 m0 : 24|8@1+ (1,-50) [-50|205] "℃"  PC
 SG_ CSC_Tpole_03_29 m0 : 32|8@1+ (1,-50) [-50|205] "℃"  PC
 SG_ CSC_Tpole_04_29 m0 : 40|8@1+ (1,-50) [-50|205] "℃"  PC
 SG_ CSC_Tpole_05_29 m0 : 48|8@1+ (1,-50) [-50|205] "℃"  PC
 SG_ CSC_Tpole_06_29 m0 : 56|8@1+ (1,-50) [-50|205] "℃"  PC

BO_ 2400644702 S2P_Detail_Tpole__30: 8 SBMU
 SG_ CSC_Tpole_No_30 : 0|8@1+ (1,0) [0|255] ""  PC
 SG_ CSC_Tpole_Frame_Index_30 M : 8|8@1+ (1,0) [0|255] ""  PC
 SG_ CSC_Tpole_01_30 m0 : 16|8@1+ (1,-50) [-50|205] "℃"  PC
 SG_ CSC_Tpole_02_30 m0 : 24|8@1+ (1,-50) [-50|205] "℃"  PC
 SG_ CSC_Tpole_03_30 m0 : 32|8@1+ (1,-50) [-50|205] "℃"  PC
 SG_ CSC_Tpole_04_30 m0 : 40|8@1+ (1,-50) [-50|205] "℃"  PC
 SG_ CSC_Tpole_05_30 m0 : 48|8@1+ (1,-50) [-50|205] "℃"  PC
 SG_ CSC_Tpole_06_30 m0 : 56|8@1+ (1,-50) [-50|205] "℃"  PC

BO_ 2400644703 S2P_Detail_Tpole__31: 8 SBMU
 SG_ CSC_Tpole_No_31 : 0|8@1+ (1,0) [0|255] ""  PC
 SG_ CSC_Tpole_Frame_Index_31 M : 8|8@1+ (1,0) [0|255] ""  PC
 SG_ CSC_Tpole_01_31 m0 : 16|8@1+ (1,-50) [-50|205] "℃"  PC
 SG_ CSC_Tpole_02_31 m0 : 24|8@1+ (1,-50) [-50|205] "℃"  PC
 SG_ CSC_Tpole_03_31 m0 : 32|8@1+ (1,-50) [-50|205] "℃"  PC
 SG_ CSC_Tpole_04_31 m0 : 40|8@1+ (1,-50) [-50|205] "℃"  PC
 SG_ CSC_Tpole_05_31 m0 : 48|8@1+ (1,-50) [-50|205] "℃"  PC
 SG_ CSC_Tpole_06_31 m0 : 56|8@1+ (1,-50) [-50|205] "℃"  PC

BO_ 2400644704 S2P_Detail_Tpole__32: 8 SBMU
 SG_ CSC_Tpole_No_32 : 0|8@1+ (1,0) [0|255] ""  PC
 SG_ CSC_Tpole_Frame_Index_32 M : 8|8@1+ (1,0) [0|255] ""  PC
 SG_ CSC_Tpole_01_32 m0 : 16|8@1+ (1,-50) [-50|205] "℃"  PC
 SG_ CSC_Tpole_02_32 m0 : 24|8@1+ (1,-50) [-50|205] "℃"  PC
 SG_ CSC_Tpole_03_32 m0 : 32|8@1+ (1,-50) [-50|205] "℃"  PC
 SG_ CSC_Tpole_04_32 m0 : 40|8@1+ (1,-50) [-50|205] "℃"  PC
 SG_ CSC_Tpole_05_32 m0 : 48|8@1+ (1,-50) [-50|205] "℃"  PC
 SG_ CSC_Tpole_06_32 m0 : 56|8@1+ (1,-50) [-50|205] "℃"  PC

BO_ 2400644705 S2P_Detail_Tpole__33: 8 SBMU
 SG_ CSC_Tpole_No_33 : 0|8@1+ (1,0) [0|255] ""  PC
 SG_ CSC_Tpole_Frame_Index_33 M : 8|8@1+ (1,0) [0|255] ""  PC
 SG_ CSC_Tpole_01_33 m0 : 16|8@1+ (1,-50) [-50|205] "℃"  PC
 SG_ CSC_Tpole_02_33 m0 : 24|8@1+ (1,-50) [-50|205] "℃"  PC
 SG_ CSC_Tpole_03_33 m0 : 32|8@1+ (1,-50) [-50|205] "℃"  PC
 SG_ CSC_Tpole_04_33 m0 : 40|8@1+ (1,-50) [-50|205] "℃"  PC
 SG_ CSC_Tpole_05_33 m0 : 48|8@1+ (1,-50) [-50|205] "℃"  PC
 SG_ CSC_Tpole_06_33 m0 : 56|8@1+ (1,-50) [-50|205] "℃"  PC

BO_ 2400644706 S2P_Detail_Tpole__34: 8 SBMU
 SG_ CSC_Tpole_No_34 : 0|8@1+ (1,0) [0|255] ""  PC
 SG_ CSC_Tpole_Frame_Index_34 M : 8|8@1+ (1,0) [0|255] ""  PC
 SG_ CSC_Tpole_01_34 m0 : 16|8@1+ (1,-50) [-50|205] "℃"  PC
 SG_ CSC_Tpole_02_34 m0 : 24|8@1+ (1,-50) [-50|205] "℃"  PC
 SG_ CSC_Tpole_03_34 m0 : 32|8@1+ (1,-50) [-50|205] "℃"  PC
 SG_ CSC_Tpole_04_34 m0 : 40|8@1+ (1,-50) [-50|205] "℃"  PC
 SG_ CSC_Tpole_05_34 m0 : 48|8@1+ (1,-50) [-50|205] "℃"  PC
 SG_ CSC_Tpole_06_34 m0 : 56|8@1+ (1,-50) [-50|205] "℃"  PC

BO_ 2400644707 S2P_Detail_Tpole__35: 8 SBMU
 SG_ CSC_Tpole_No_35 : 0|8@1+ (1,0) [0|255] ""  PC
 SG_ CSC_Tpole_Frame_Index_35 M : 8|8@1+ (1,0) [0|255] ""  PC
 SG_ CSC_Tpole_01_35 m0 : 16|8@1+ (1,-50) [-50|205] "℃"  PC
 SG_ CSC_Tpole_02_35 m0 : 24|8@1+ (1,-50) [-50|205] "℃"  PC
 SG_ CSC_Tpole_03_35 m0 : 32|8@1+ (1,-50) [-50|205] "℃"  PC
 SG_ CSC_Tpole_04_35 m0 : 40|8@1+ (1,-50) [-50|205] "℃"  PC
 SG_ CSC_Tpole_05_35 m0 : 48|8@1+ (1,-50) [-50|205] "℃"  PC
 SG_ CSC_Tpole_06_35 m0 : 56|8@1+ (1,-50) [-50|205] "℃"  PC

BO_ 2400644708 S2P_Detail_Tpole__36: 8 SBMU
 SG_ CSC_Tpole_No_36 : 0|8@1+ (1,0) [0|255] ""  PC
 SG_ CSC_Tpole_Frame_Index_36 M : 8|8@1+ (1,0) [0|255] ""  PC
 SG_ CSC_Tpole_01_36 m0 : 16|8@1+ (1,-50) [-50|205] "℃"  PC
 SG_ CSC_Tpole_02_36 m0 : 24|8@1+ (1,-50) [-50|205] "℃"  PC
 SG_ CSC_Tpole_03_36 m0 : 32|8@1+ (1,-50) [-50|205] "℃"  PC
 SG_ CSC_Tpole_04_36 m0 : 40|8@1+ (1,-50) [-50|205] "℃"  PC
 SG_ CSC_Tpole_05_36 m0 : 48|8@1+ (1,-50) [-50|205] "℃"  PC
 SG_ CSC_Tpole_06_36 m0 : 56|8@1+ (1,-50) [-50|205] "℃"  PC

BO_ 2400644709 S2P_Detail_Tpole__37: 8 SBMU
 SG_ CSC_Tpole_No_37 : 0|8@1+ (1,0) [0|255] ""  PC
 SG_ CSC_Tpole_Frame_Index_37 M : 8|8@1+ (1,0) [0|255] ""  PC
 SG_ CSC_Tpole_01_37 m0 : 16|8@1+ (1,-50) [-50|205] "℃"  PC
 SG_ CSC_Tpole_02_37 m0 : 24|8@1+ (1,-50) [-50|205] "℃"  PC
 SG_ CSC_Tpole_03_37 m0 : 32|8@1+ (1,-50) [-50|205] "℃"  PC
 SG_ CSC_Tpole_04_37 m0 : 40|8@1+ (1,-50) [-50|205] "℃"  PC
 SG_ CSC_Tpole_05_37 m0 : 48|8@1+ (1,-50) [-50|205] "℃"  PC
 SG_ CSC_Tpole_06_37 m0 : 56|8@1+ (1,-50) [-50|205] "℃"  PC

BO_ 2400644710 S2P_Detail_Tpole__38: 8 SBMU
 SG_ CSC_Tpole_No_38 : 0|8@1+ (1,0) [0|255] ""  PC
 SG_ CSC_Tpole_Frame_Index_38 M : 8|8@1+ (1,0) [0|255] ""  PC
 SG_ CSC_Tpole_01_38 m0 : 16|8@1+ (1,-50) [-50|205] "℃"  PC
 SG_ CSC_Tpole_02_38 m0 : 24|8@1+ (1,-50) [-50|205] "℃"  PC
 SG_ CSC_Tpole_03_38 m0 : 32|8@1+ (1,-50) [-50|205] "℃"  PC
 SG_ CSC_Tpole_04_38 m0 : 40|8@1+ (1,-50) [-50|205] "℃"  PC
 SG_ CSC_Tpole_05_38 m0 : 48|8@1+ (1,-50) [-50|205] "℃"  PC
 SG_ CSC_Tpole_06_38 m0 : 56|8@1+ (1,-50) [-50|205] "℃"  PC

BO_ 2400644711 S2P_Detail_Tpole__39: 8 SBMU
 SG_ CSC_Tpole_No_39 : 0|8@1+ (1,0) [0|255] ""  PC
 SG_ CSC_Tpole_Frame_Index_39 M : 8|8@1+ (1,0) [0|255] ""  PC
 SG_ CSC_Tpole_01_39 m0 : 16|8@1+ (1,-50) [-50|205] "℃"  PC
 SG_ CSC_Tpole_02_39 m0 : 24|8@1+ (1,-50) [-50|205] "℃"  PC
 SG_ CSC_Tpole_03_39 m0 : 32|8@1+ (1,-50) [-50|205] "℃"  PC
 SG_ CSC_Tpole_04_39 m0 : 40|8@1+ (1,-50) [-50|205] "℃"  PC
 SG_ CSC_Tpole_05_39 m0 : 48|8@1+ (1,-50) [-50|205] "℃"  PC
 SG_ CSC_Tpole_06_39 m0 : 56|8@1+ (1,-50) [-50|205] "℃"  PC

BO_ 2400644712 S2P_Detail_Tpole__40: 8 SBMU
 SG_ CSC_Tpole_No_40 : 0|8@1+ (1,0) [0|255] ""  PC
 SG_ CSC_Tpole_Frame_Index_40 M : 8|8@1+ (1,0) [0|255] ""  PC
 SG_ CSC_Tpole_01_40 m0 : 16|8@1+ (1,-50) [-50|205] "℃"  PC
 SG_ CSC_Tpole_02_40 m0 : 24|8@1+ (1,-50) [-50|205] "℃"  PC
 SG_ CSC_Tpole_03_40 m0 : 32|8@1+ (1,-50) [-50|205] "℃"  PC
 SG_ CSC_Tpole_04_40 m0 : 40|8@1+ (1,-50) [-50|205] "℃"  PC
 SG_ CSC_Tpole_05_40 m0 : 48|8@1+ (1,-50) [-50|205] "℃"  PC
 SG_ CSC_Tpole_06_40 m0 : 56|8@1+ (1,-50) [-50|205] "℃"  PC

BO_ 2400644713 S2P_Detail_Tpole__41: 8 SBMU
 SG_ CSC_Tpole_No_41 : 0|8@1+ (1,0) [0|255] ""  PC
 SG_ CSC_Tpole_Frame_Index_41 M : 8|8@1+ (1,0) [0|255] ""  PC
 SG_ CSC_Tpole_01_41 m0 : 16|8@1+ (1,-50) [-50|205] "℃"  PC
 SG_ CSC_Tpole_02_41 m0 : 24|8@1+ (1,-50) [-50|205] "℃"  PC
 SG_ CSC_Tpole_03_41 m0 : 32|8@1+ (1,-50) [-50|205] "℃"  PC
 SG_ CSC_Tpole_04_41 m0 : 40|8@1+ (1,-50) [-50|205] "℃"  PC
 SG_ CSC_Tpole_05_41 m0 : 48|8@1+ (1,-50) [-50|205] "℃"  PC
 SG_ CSC_Tpole_06_41 m0 : 56|8@1+ (1,-50) [-50|205] "℃"  PC

BO_ 2400644714 S2P_Detail_Tpole__42: 8 SBMU
 SG_ CSC_Tpole_No_42 : 0|8@1+ (1,0) [0|255] ""  PC
 SG_ CSC_Tpole_Frame_Index_42 M : 8|8@1+ (1,0) [0|255] ""  PC
 SG_ CSC_Tpole_01_42 m0 : 16|8@1+ (1,-50) [-50|205] "℃"  PC
 SG_ CSC_Tpole_02_42 m0 : 24|8@1+ (1,-50) [-50|205] "℃"  PC
 SG_ CSC_Tpole_03_42 m0 : 32|8@1+ (1,-50) [-50|205] "℃"  PC
 SG_ CSC_Tpole_04_42 m0 : 40|8@1+ (1,-50) [-50|205] "℃"  PC
 SG_ CSC_Tpole_05_42 m0 : 48|8@1+ (1,-50) [-50|205] "℃"  PC
 SG_ CSC_Tpole_06_42 m0 : 56|8@1+ (1,-50) [-50|205] "℃"  PC

BO_ 2400644715 S2P_Detail_Tpole__43: 8 SBMU
 SG_ CSC_Tpole_No_43 : 0|8@1+ (1,0) [0|255] ""  PC
 SG_ CSC_Tpole_Frame_Index_43 M : 8|8@1+ (1,0) [0|255] ""  PC
 SG_ CSC_Tpole_01_43 m0 : 16|8@1+ (1,-50) [-50|205] "℃"  PC
 SG_ CSC_Tpole_02_43 m0 : 24|8@1+ (1,-50) [-50|205] "℃"  PC
 SG_ CSC_Tpole_03_43 m0 : 32|8@1+ (1,-50) [-50|205] "℃"  PC
 SG_ CSC_Tpole_04_43 m0 : 40|8@1+ (1,-50) [-50|205] "℃"  PC
 SG_ CSC_Tpole_05_43 m0 : 48|8@1+ (1,-50) [-50|205] "℃"  PC
 SG_ CSC_Tpole_06_43 m0 : 56|8@1+ (1,-50) [-50|205] "℃"  PC

BO_ 2400644716 S2P_Detail_Tpole__44: 8 SBMU
 SG_ CSC_Tpole_No_44 : 0|8@1+ (1,0) [0|255] ""  PC
 SG_ CSC_Tpole_Frame_Index_44 M : 8|8@1+ (1,0) [0|255] ""  PC
 SG_ CSC_Tpole_01_44 m0 : 16|8@1+ (1,-50) [-50|205] "℃"  PC
 SG_ CSC_Tpole_02_44 m0 : 24|8@1+ (1,-50) [-50|205] "℃"  PC
 SG_ CSC_Tpole_03_44 m0 : 32|8@1+ (1,-50) [-50|205] "℃"  PC
 SG_ CSC_Tpole_04_44 m0 : 40|8@1+ (1,-50) [-50|205] "℃"  PC
 SG_ CSC_Tpole_05_44 m0 : 48|8@1+ (1,-50) [-50|205] "℃"  PC
 SG_ CSC_Tpole_06_44 m0 : 56|8@1+ (1,-50) [-50|205] "℃"  PC

BO_ 2400644717 S2P_Detail_Tpole__45: 8 SBMU
 SG_ CSC_Tpole_No_45 : 0|8@1+ (1,0) [0|255] ""  PC
 SG_ CSC_Tpole_Frame_Index_45 M : 8|8@1+ (1,0) [0|255] ""  PC
 SG_ CSC_Tpole_01_45 m0 : 16|8@1+ (1,-50) [-50|205] "℃"  PC
 SG_ CSC_Tpole_02_45 m0 : 24|8@1+ (1,-50) [-50|205] "℃"  PC
 SG_ CSC_Tpole_03_45 m0 : 32|8@1+ (1,-50) [-50|205] "℃"  PC
 SG_ CSC_Tpole_04_45 m0 : 40|8@1+ (1,-50) [-50|205] "℃"  PC
 SG_ CSC_Tpole_05_45 m0 : 48|8@1+ (1,-50) [-50|205] "℃"  PC
 SG_ CSC_Tpole_06_45 m0 : 56|8@1+ (1,-50) [-50|205] "℃"  PC

BO_ 2400644718 S2P_Detail_Tpole__46: 8 SBMU
 SG_ CSC_Tpole_No_46 : 0|8@1+ (1,0) [0|255] ""  PC
 SG_ CSC_Tpole_Frame_Index_46 M : 8|8@1+ (1,0) [0|255] ""  PC
 SG_ CSC_Tpole_01_46 m0 : 16|8@1+ (1,-50) [-50|205] "℃"  PC
 SG_ CSC_Tpole_02_46 m0 : 24|8@1+ (1,-50) [-50|205] "℃"  PC
 SG_ CSC_Tpole_03_46 m0 : 32|8@1+ (1,-50) [-50|205] "℃"  PC
 SG_ CSC_Tpole_04_46 m0 : 40|8@1+ (1,-50) [-50|205] "℃"  PC
 SG_ CSC_Tpole_05_46 m0 : 48|8@1+ (1,-50) [-50|205] "℃"  PC
 SG_ CSC_Tpole_06_46 m0 : 56|8@1+ (1,-50) [-50|205] "℃"  PC

BO_ 2400644719 S2P_Detail_Tpole__47: 8 SBMU
 SG_ CSC_Tpole_No_47 : 0|8@1+ (1,0) [0|255] ""  PC
 SG_ CSC_Tpole_Frame_Index_47 M : 8|8@1+ (1,0) [0|255] ""  PC
 SG_ CSC_Tpole_01_47 m0 : 16|8@1+ (1,-50) [-50|205] "℃"  PC
 SG_ CSC_Tpole_02_47 m0 : 24|8@1+ (1,-50) [-50|205] "℃"  PC
 SG_ CSC_Tpole_03_47 m0 : 32|8@1+ (1,-50) [-50|205] "℃"  PC
 SG_ CSC_Tpole_04_47 m0 : 40|8@1+ (1,-50) [-50|205] "℃"  PC
 SG_ CSC_Tpole_05_47 m0 : 48|8@1+ (1,-50) [-50|205] "℃"  PC
 SG_ CSC_Tpole_06_47 m0 : 56|8@1+ (1,-50) [-50|205] "℃"  PC

BO_ 2400644720 S2P_Detail_Tpole__48: 8 SBMU
 SG_ CSC_Tpole_No_48 : 0|8@1+ (1,0) [0|255] ""  PC
 SG_ CSC_Tpole_Frame_Index_48 M : 8|8@1+ (1,0) [0|255] ""  PC
 SG_ CSC_Tpole_01_48 m0 : 16|8@1+ (1,-50) [-50|205] "℃"  PC
 SG_ CSC_Tpole_02_48 m0 : 24|8@1+ (1,-50) [-50|205] "℃"  PC
 SG_ CSC_Tpole_03_48 m0 : 32|8@1+ (1,-50) [-50|205] "℃"  PC
 SG_ CSC_Tpole_04_48 m0 : 40|8@1+ (1,-50) [-50|205] "℃"  PC
 SG_ CSC_Tpole_05_48 m0 : 48|8@1+ (1,-50) [-50|205] "℃"  PC
 SG_ CSC_Tpole_06_48 m0 : 56|8@1+ (1,-50) [-50|205] "℃"  PC

BO_ 2400644721 S2P_Detail_Tpole__49: 8 SBMU
 SG_ CSC_Tpole_No_49 : 0|8@1+ (1,0) [0|255] ""  PC
 SG_ CSC_Tpole_Frame_Index_49 M : 8|8@1+ (1,0) [0|255] ""  PC
 SG_ CSC_Tpole_01_49 m0 : 16|8@1+ (1,-50) [-50|205] "℃"  PC
 SG_ CSC_Tpole_02_49 m0 : 24|8@1+ (1,-50) [-50|205] "℃"  PC
 SG_ CSC_Tpole_03_49 m0 : 32|8@1+ (1,-50) [-50|205] "℃"  PC
 SG_ CSC_Tpole_04_49 m0 : 40|8@1+ (1,-50) [-50|205] "℃"  PC
 SG_ CSC_Tpole_05_49 m0 : 48|8@1+ (1,-50) [-50|205] "℃"  PC
 SG_ CSC_Tpole_06_49 m0 : 56|8@1+ (1,-50) [-50|205] "℃"  PC

BO_ 2400644722 S2P_Detail_Tpole__50: 8 SBMU
 SG_ CSC_Tpole_No_50 : 0|8@1+ (1,0) [0|255] ""  PC
 SG_ CSC_Tpole_Frame_Index_50 M : 8|8@1+ (1,0) [0|255] ""  PC
 SG_ CSC_Tpole_01_50 m0 : 16|8@1+ (1,-50) [-50|205] "℃"  PC
 SG_ CSC_Tpole_02_50 m0 : 24|8@1+ (1,-50) [-50|205] "℃"  PC
 SG_ CSC_Tpole_03_50 m0 : 32|8@1+ (1,-50) [-50|205] "℃"  PC
 SG_ CSC_Tpole_04_50 m0 : 40|8@1+ (1,-50) [-50|205] "℃"  PC
 SG_ CSC_Tpole_05_50 m0 : 48|8@1+ (1,-50) [-50|205] "℃"  PC
 SG_ CSC_Tpole_06_50 m0 : 56|8@1+ (1,-50) [-50|205] "℃"  PC

BO_ 2400644723 S2P_Detail_Tpole__51: 8 SBMU
 SG_ CSC_Tpole_No_51 : 0|8@1+ (1,0) [0|255] ""  PC
 SG_ CSC_Tpole_Frame_Index_51 M : 8|8@1+ (1,0) [0|255] ""  PC
 SG_ CSC_Tpole_01_51 m0 : 16|8@1+ (1,-50) [-50|205] "℃"  PC
 SG_ CSC_Tpole_02_51 m0 : 24|8@1+ (1,-50) [-50|205] "℃"  PC
 SG_ CSC_Tpole_03_51 m0 : 32|8@1+ (1,-50) [-50|205] "℃"  PC
 SG_ CSC_Tpole_04_51 m0 : 40|8@1+ (1,-50) [-50|205] "℃"  PC
 SG_ CSC_Tpole_05_51 m0 : 48|8@1+ (1,-50) [-50|205] "℃"  PC
 SG_ CSC_Tpole_06_51 m0 : 56|8@1+ (1,-50) [-50|205] "℃"  PC

BO_ 2400644724 S2P_Detail_Tpole__52: 8 SBMU
 SG_ CSC_Tpole_No_52 : 0|8@1+ (1,0) [0|255] ""  PC
 SG_ CSC_Tpole_Frame_Index_52 M : 8|8@1+ (1,0) [0|255] ""  PC
 SG_ CSC_Tpole_01_52 m0 : 16|8@1+ (1,-50) [-50|205] "℃"  PC
 SG_ CSC_Tpole_02_52 m0 : 24|8@1+ (1,-50) [-50|205] "℃"  PC
 SG_ CSC_Tpole_03_52 m0 : 32|8@1+ (1,-50) [-50|205] "℃"  PC
 SG_ CSC_Tpole_04_52 m0 : 40|8@1+ (1,-50) [-50|205] "℃"  PC
 SG_ CSC_Tpole_05_52 m0 : 48|8@1+ (1,-50) [-50|205] "℃"  PC
 SG_ CSC_Tpole_06_52 m0 : 56|8@1+ (1,-50) [-50|205] "℃"  PC

BO_ 2400644725 S2P_Detail_Tpole__53: 8 SBMU
 SG_ CSC_Tpole_No_53 : 0|8@1+ (1,0) [0|255] ""  PC
 SG_ CSC_Tpole_Frame_Index_53 M : 8|8@1+ (1,0) [0|255] ""  PC
 SG_ CSC_Tpole_01_53 m0 : 16|8@1+ (1,-50) [-50|205] "℃"  PC
 SG_ CSC_Tpole_02_53 m0 : 24|8@1+ (1,-50) [-50|205] "℃"  PC
 SG_ CSC_Tpole_03_53 m0 : 32|8@1+ (1,-50) [-50|205] "℃"  PC
 SG_ CSC_Tpole_04_53 m0 : 40|8@1+ (1,-50) [-50|205] "℃"  PC
 SG_ CSC_Tpole_05_53 m0 : 48|8@1+ (1,-50) [-50|205] "℃"  PC
 SG_ CSC_Tpole_06_53 m0 : 56|8@1+ (1,-50) [-50|205] "℃"  PC

BO_ 2400644726 S2P_Detail_Tpole__54: 8 SBMU
 SG_ CSC_Tpole_No_54 : 0|8@1+ (1,0) [0|255] ""  PC
 SG_ CSC_Tpole_Frame_Index_54 M : 8|8@1+ (1,0) [0|255] ""  PC
 SG_ CSC_Tpole_01_54 m0 : 16|8@1+ (1,-50) [-50|205] "℃"  PC
 SG_ CSC_Tpole_02_54 m0 : 24|8@1+ (1,-50) [-50|205] "℃"  PC
 SG_ CSC_Tpole_03_54 m0 : 32|8@1+ (1,-50) [-50|205] "℃"  PC
 SG_ CSC_Tpole_04_54 m0 : 40|8@1+ (1,-50) [-50|205] "℃"  PC
 SG_ CSC_Tpole_05_54 m0 : 48|8@1+ (1,-50) [-50|205] "℃"  PC
 SG_ CSC_Tpole_06_54 m0 : 56|8@1+ (1,-50) [-50|205] "℃"  PC

BO_ 2400644727 S2P_Detail_Tpole__55: 8 SBMU
 SG_ CSC_Tpole_No_55 : 0|8@1+ (1,0) [0|255] ""  PC
 SG_ CSC_Tpole_Frame_Index_55 M : 8|8@1+ (1,0) [0|255] ""  PC
 SG_ CSC_Tpole_01_55 m0 : 16|8@1+ (1,-50) [-50|205] "℃"  PC
 SG_ CSC_Tpole_02_55 m0 : 24|8@1+ (1,-50) [-50|205] "℃"  PC
 SG_ CSC_Tpole_03_55 m0 : 32|8@1+ (1,-50) [-50|205] "℃"  PC
 SG_ CSC_Tpole_04_55 m0 : 40|8@1+ (1,-50) [-50|205] "℃"  PC
 SG_ CSC_Tpole_05_55 m0 : 48|8@1+ (1,-50) [-50|205] "℃"  PC
 SG_ CSC_Tpole_06_55 m0 : 56|8@1+ (1,-50) [-50|205] "℃"  PC

BO_ 2400644728 S2P_Detail_Tpole__56: 8 SBMU
 SG_ CSC_Tpole_No_56 : 0|8@1+ (1,0) [0|255] ""  PC
 SG_ CSC_Tpole_Frame_Index_56 M : 8|8@1+ (1,0) [0|255] ""  PC
 SG_ CSC_Tpole_01_56 m0 : 16|8@1+ (1,-50) [-50|205] "℃"  PC
 SG_ CSC_Tpole_02_56 m0 : 24|8@1+ (1,-50) [-50|205] "℃"  PC
 SG_ CSC_Tpole_03_56 m0 : 32|8@1+ (1,-50) [-50|205] "℃"  PC
 SG_ CSC_Tpole_04_56 m0 : 40|8@1+ (1,-50) [-50|205] "℃"  PC
 SG_ CSC_Tpole_05_56 m0 : 48|8@1+ (1,-50) [-50|205] "℃"  PC
 SG_ CSC_Tpole_06_56 m0 : 56|8@1+ (1,-50) [-50|205] "℃"  PC

BO_ 2400644729 S2P_Detail_Tpole__57: 8 SBMU
 SG_ CSC_Tpole_No_57 : 0|8@1+ (1,0) [0|255] ""  PC
 SG_ CSC_Tpole_Frame_Index_57 M : 8|8@1+ (1,0) [0|255] ""  PC
 SG_ CSC_Tpole_01_57 m0 : 16|8@1+ (1,-50) [-50|205] "℃"  PC
 SG_ CSC_Tpole_02_57 m0 : 24|8@1+ (1,-50) [-50|205] "℃"  PC
 SG_ CSC_Tpole_03_57 m0 : 32|8@1+ (1,-50) [-50|205] "℃"  PC
 SG_ CSC_Tpole_04_57 m0 : 40|8@1+ (1,-50) [-50|205] "℃"  PC
 SG_ CSC_Tpole_05_57 m0 : 48|8@1+ (1,-50) [-50|205] "℃"  PC
 SG_ CSC_Tpole_06_57 m0 : 56|8@1+ (1,-50) [-50|205] "℃"  PC

BO_ 2400644730 S2P_Detail_Tpole__58: 8 SBMU
 SG_ CSC_Tpole_No_58 : 0|8@1+ (1,0) [0|255] ""  PC
 SG_ CSC_Tpole_Frame_Index_58 M : 8|8@1+ (1,0) [0|255] ""  PC
 SG_ CSC_Tpole_01_58 m0 : 16|8@1+ (1,-50) [-50|205] "℃"  PC
 SG_ CSC_Tpole_02_58 m0 : 24|8@1+ (1,-50) [-50|205] "℃"  PC
 SG_ CSC_Tpole_03_58 m0 : 32|8@1+ (1,-50) [-50|205] "℃"  PC
 SG_ CSC_Tpole_04_58 m0 : 40|8@1+ (1,-50) [-50|205] "℃"  PC
 SG_ CSC_Tpole_05_58 m0 : 48|8@1+ (1,-50) [-50|205] "℃"  PC
 SG_ CSC_Tpole_06_58 m0 : 56|8@1+ (1,-50) [-50|205] "℃"  PC

BO_ 2400644731 S2P_Detail_Tpole__59: 8 SBMU
 SG_ CSC_Tpole_No_59 : 0|8@1+ (1,0) [0|255] ""  PC
 SG_ CSC_Tpole_Frame_Index_59 M : 8|8@1+ (1,0) [0|255] ""  PC
 SG_ CSC_Tpole_01_59 m0 : 16|8@1+ (1,-50) [-50|205] "℃"  PC
 SG_ CSC_Tpole_02_59 m0 : 24|8@1+ (1,-50) [-50|205] "℃"  PC
 SG_ CSC_Tpole_03_59 m0 : 32|8@1+ (1,-50) [-50|205] "℃"  PC
 SG_ CSC_Tpole_04_59 m0 : 40|8@1+ (1,-50) [-50|205] "℃"  PC
 SG_ CSC_Tpole_05_59 m0 : 48|8@1+ (1,-50) [-50|205] "℃"  PC
 SG_ CSC_Tpole_06_59 m0 : 56|8@1+ (1,-50) [-50|205] "℃"  PC

BO_ 2400644732 S2P_Detail_Tpole__60: 8 SBMU
 SG_ CSC_Tpole_No_60 : 0|8@1+ (1,0) [0|255] ""  PC
 SG_ CSC_Tpole_Frame_Index_60 M : 8|8@1+ (1,0) [0|255] ""  PC
 SG_ CSC_Tpole_01_60 m0 : 16|8@1+ (1,-50) [-50|205] "℃"  PC
 SG_ CSC_Tpole_02_60 m0 : 24|8@1+ (1,-50) [-50|205] "℃"  PC
 SG_ CSC_Tpole_03_60 m0 : 32|8@1+ (1,-50) [-50|205] "℃"  PC
 SG_ CSC_Tpole_04_60 m0 : 40|8@1+ (1,-50) [-50|205] "℃"  PC
 SG_ CSC_Tpole_05_60 m0 : 48|8@1+ (1,-50) [-50|205] "℃"  PC
 SG_ CSC_Tpole_06_60 m0 : 56|8@1+ (1,-50) [-50|205] "℃"  PC

BO_ 2400644733 S2P_Detail_Tpole__61: 8 SBMU
 SG_ CSC_Tpole_No_61 : 0|8@1+ (1,0) [0|255] ""  PC
 SG_ CSC_Tpole_Frame_Index_61 M : 8|8@1+ (1,0) [0|255] ""  PC
 SG_ CSC_Tpole_01_61 m0 : 16|8@1+ (1,-50) [-50|205] "℃"  PC
 SG_ CSC_Tpole_02_61 m0 : 24|8@1+ (1,-50) [-50|205] "℃"  PC
 SG_ CSC_Tpole_03_61 m0 : 32|8@1+ (1,-50) [-50|205] "℃"  PC
 SG_ CSC_Tpole_04_61 m0 : 40|8@1+ (1,-50) [-50|205] "℃"  PC
 SG_ CSC_Tpole_05_61 m0 : 48|8@1+ (1,-50) [-50|205] "℃"  PC
 SG_ CSC_Tpole_06_61 m0 : 56|8@1+ (1,-50) [-50|205] "℃"  PC

BO_ 2400644734 S2P_Detail_Tpole__62: 8 SBMU
 SG_ CSC_Tpole_No_62 : 0|8@1+ (1,0) [0|255] ""  PC
 SG_ CSC_Tpole_Frame_Index_62 M : 8|8@1+ (1,0) [0|255] ""  PC
 SG_ CSC_Tpole_01_62 m0 : 16|8@1+ (1,-50) [-50|205] "℃"  PC
 SG_ CSC_Tpole_02_62 m0 : 24|8@1+ (1,-50) [-50|205] "℃"  PC
 SG_ CSC_Tpole_03_62 m0 : 32|8@1+ (1,-50) [-50|205] "℃"  PC
 SG_ CSC_Tpole_04_62 m0 : 40|8@1+ (1,-50) [-50|205] "℃"  PC
 SG_ CSC_Tpole_05_62 m0 : 48|8@1+ (1,-50) [-50|205] "℃"  PC
 SG_ CSC_Tpole_06_62 m0 : 56|8@1+ (1,-50) [-50|205] "℃"  PC

BO_ 2400644735 S2P_Detail_Tpole__63: 8 SBMU
 SG_ CSC_Tpole_No_63 : 0|8@1+ (1,0) [0|255] ""  PC
 SG_ CSC_Tpole_Frame_Index_63 M : 8|8@1+ (1,0) [0|255] ""  PC
 SG_ CSC_Tpole_01_63 m0 : 16|8@1+ (1,-50) [-50|205] "℃"  PC
 SG_ CSC_Tpole_02_63 m0 : 24|8@1+ (1,-50) [-50|205] "℃"  PC
 SG_ CSC_Tpole_03_63 m0 : 32|8@1+ (1,-50) [-50|205] "℃"  PC
 SG_ CSC_Tpole_04_63 m0 : 40|8@1+ (1,-50) [-50|205] "℃"  PC
 SG_ CSC_Tpole_05_63 m0 : 48|8@1+ (1,-50) [-50|205] "℃"  PC
 SG_ CSC_Tpole_06_63 m0 : 56|8@1+ (1,-50) [-50|205] "℃"  PC

BO_ 2332618385 M2P_SUMDATA8__01: 8 MBMU
 SG_ M2P_SysMaxVolt_HvOn_01 : 0|16@1+ (1,0) [0|65535] "mV"  PC
 SG_ M2P_SysMinVolt_HvOn_01 : 16|16@1+ (1,0) [0|65535] "mV"  PC
 SG_ M2P_SysAvgVolt_HvOn_01 : 32|16@1+ (1,0) [0|65535] "mV"  PC

BO_ 2332618386 M2P_SUMDATA8__02: 8 MBMU
 SG_ M2P_SysMaxVolt_HvOn_02 : 0|16@1+ (1,0) [0|65535] "mV"  PC
 SG_ M2P_SysMinVolt_HvOn_02 : 16|16@1+ (1,0) [0|65535] "mV"  PC
 SG_ M2P_SysAvgVolt_HvOn_02 : 32|16@1+ (1,0) [0|65535] "mV"  PC

BO_ 2332618387 M2P_SUMDATA8__03: 8 MBMU
 SG_ M2P_SysMaxVolt_HvOn_03 : 0|16@1+ (1,0) [0|65535] "mV"  PC
 SG_ M2P_SysMinVolt_HvOn_03 : 16|16@1+ (1,0) [0|65535] "mV"  PC
 SG_ M2P_SysAvgVolt_HvOn_03 : 32|16@1+ (1,0) [0|65535] "mV"  PC

BO_ 2332618388 M2P_SUMDATA8__04: 8 MBMU
 SG_ M2P_SysMaxVolt_HvOn_04 : 0|16@1+ (1,0) [0|65535] "mV"  PC
 SG_ M2P_SysMinVolt_HvOn_04 : 16|16@1+ (1,0) [0|65535] "mV"  PC
 SG_ M2P_SysAvgVolt_HvOn_04 : 32|16@1+ (1,0) [0|65535] "mV"  PC

BO_ 2332618389 M2P_SUMDATA8__05: 8 MBMU
 SG_ M2P_SysMaxVolt_HvOn_05 : 0|16@1+ (1,0) [0|65535] "mV"  PC
 SG_ M2P_SysMinVolt_HvOn_05 : 16|16@1+ (1,0) [0|65535] "mV"  PC
 SG_ M2P_SysAvgVolt_HvOn_05 : 32|16@1+ (1,0) [0|65535] "mV"  PC

BO_ 2332618390 M2P_SUMDATA8__06: 8 MBMU
 SG_ M2P_SysMaxVolt_HvOn_06 : 0|16@1+ (1,0) [0|65535] "mV"  PC
 SG_ M2P_SysMinVolt_HvOn_06 : 16|16@1+ (1,0) [0|65535] "mV"  PC
 SG_ M2P_SysAvgVolt_HvOn_06 : 32|16@1+ (1,0) [0|65535] "mV"  PC

BO_ 2332618391 M2P_SUMDATA8__07: 8 MBMU
 SG_ M2P_SysMaxVolt_HvOn_07 : 0|16@1+ (1,0) [0|65535] "mV"  PC
 SG_ M2P_SysMinVolt_HvOn_07 : 16|16@1+ (1,0) [0|65535] "mV"  PC
 SG_ M2P_SysAvgVolt_HvOn_07 : 32|16@1+ (1,0) [0|65535] "mV"  PC

BO_ 2332618392 M2P_SUMDATA8__08: 8 MBMU
 SG_ M2P_SysMaxVolt_HvOn_08 : 0|16@1+ (1,0) [0|65535] "mV"  PC
 SG_ M2P_SysMinVolt_HvOn_08 : 16|16@1+ (1,0) [0|65535] "mV"  PC
 SG_ M2P_SysAvgVolt_HvOn_08 : 32|16@1+ (1,0) [0|65535] "mV"  PC

BO_ 2332618393 M2P_SUMDATA8__09: 8 MBMU
 SG_ M2P_SysMaxVolt_HvOn_09 : 0|16@1+ (1,0) [0|65535] "mV"  PC
 SG_ M2P_SysMinVolt_HvOn_09 : 16|16@1+ (1,0) [0|65535] "mV"  PC
 SG_ M2P_SysAvgVolt_HvOn_09 : 32|16@1+ (1,0) [0|65535] "mV"  PC

BO_ 2332618394 M2P_SUMDATA8__10: 8 MBMU
 SG_ M2P_SysMaxVolt_HvOn_10 : 0|16@1+ (1,0) [0|65535] "mV"  PC
 SG_ M2P_SysMinVolt_HvOn_10 : 16|16@1+ (1,0) [0|65535] "mV"  PC
 SG_ M2P_SysAvgVolt_HvOn_10 : 32|16@1+ (1,0) [0|65535] "mV"  PC

BO_ 2332618395 M2P_SUMDATA8__11: 8 MBMU
 SG_ M2P_SysMaxVolt_HvOn_11 : 0|16@1+ (1,0) [0|65535] "mV"  PC
 SG_ M2P_SysMinVolt_HvOn_11 : 16|16@1+ (1,0) [0|65535] "mV"  PC
 SG_ M2P_SysAvgVolt_HvOn_11 : 32|16@1+ (1,0) [0|65535] "mV"  PC

BO_ 2332618396 M2P_SUMDATA8__12: 8 MBMU
 SG_ M2P_SysMaxVolt_HvOn_12 : 0|16@1+ (1,0) [0|65535] "mV"  PC
 SG_ M2P_SysMinVolt_HvOn_12 : 16|16@1+ (1,0) [0|65535] "mV"  PC
 SG_ M2P_SysAvgVolt_HvOn_12 : 32|16@1+ (1,0) [0|65535] "mV"  PC

BO_ 2332618397 M2P_SUMDATA8__13: 8 MBMU
 SG_ M2P_SysMaxVolt_HvOn_13 : 0|16@1+ (1,0) [0|65535] "mV"  PC
 SG_ M2P_SysMinVolt_HvOn_13 : 16|16@1+ (1,0) [0|65535] "mV"  PC
 SG_ M2P_SysAvgVolt_HvOn_13 : 32|16@1+ (1,0) [0|65535] "mV"  PC

BO_ 2332618398 M2P_SUMDATA8__14: 8 MBMU
 SG_ M2P_SysMaxVolt_HvOn_14 : 0|16@1+ (1,0) [0|65535] "mV"  PC
 SG_ M2P_SysMinVolt_HvOn_14 : 16|16@1+ (1,0) [0|65535] "mV"  PC
 SG_ M2P_SysAvgVolt_HvOn_14 : 32|16@1+ (1,0) [0|65535] "mV"  PC

BO_ 2332618399 M2P_SUMDATA8__15: 8 MBMU
 SG_ M2P_SysMaxVolt_HvOn_15 : 0|16@1+ (1,0) [0|65535] "mV"  PC
 SG_ M2P_SysMinVolt_HvOn_15 : 16|16@1+ (1,0) [0|65535] "mV"  PC
 SG_ M2P_SysAvgVolt_HvOn_15 : 32|16@1+ (1,0) [0|65535] "mV"  PC

BO_ 2332618400 M2P_SUMDATA8__16: 8 MBMU
 SG_ M2P_SysMaxVolt_HvOn_16 : 0|16@1+ (1,0) [0|65535] "mV"  PC
 SG_ M2P_SysMinVolt_HvOn_16 : 16|16@1+ (1,0) [0|65535] "mV"  PC
 SG_ M2P_SysAvgVolt_HvOn_16 : 32|16@1+ (1,0) [0|65535] "mV"  PC

BO_ 2332618401 M2P_SUMDATA8__17: 8 MBMU
 SG_ M2P_SysMaxVolt_HvOn_17 : 0|16@1+ (1,0) [0|65535] "mV"  PC
 SG_ M2P_SysMinVolt_HvOn_17 : 16|16@1+ (1,0) [0|65535] "mV"  PC
 SG_ M2P_SysAvgVolt_HvOn_17 : 32|16@1+ (1,0) [0|65535] "mV"  PC

BO_ 2332618402 M2P_SUMDATA8__18: 8 MBMU
 SG_ M2P_SysMaxVolt_HvOn_18 : 0|16@1+ (1,0) [0|65535] "mV"  PC
 SG_ M2P_SysMinVolt_HvOn_18 : 16|16@1+ (1,0) [0|65535] "mV"  PC
 SG_ M2P_SysAvgVolt_HvOn_18 : 32|16@1+ (1,0) [0|65535] "mV"  PC

BO_ 2332618403 M2P_SUMDATA8__19: 8 MBMU
 SG_ M2P_SysMaxVolt_HvOn_19 : 0|16@1+ (1,0) [0|65535] "mV"  PC
 SG_ M2P_SysMinVolt_HvOn_19 : 16|16@1+ (1,0) [0|65535] "mV"  PC
 SG_ M2P_SysAvgVolt_HvOn_19 : 32|16@1+ (1,0) [0|65535] "mV"  PC

BO_ 2332618404 M2P_SUMDATA8__20: 8 MBMU
 SG_ M2P_SysMaxVolt_HvOn_20 : 0|16@1+ (1,0) [0|65535] "mV"  PC
 SG_ M2P_SysMinVolt_HvOn_20 : 16|16@1+ (1,0) [0|65535] "mV"  PC
 SG_ M2P_SysAvgVolt_HvOn_20 : 32|16@1+ (1,0) [0|65535] "mV"  PC

BO_ 2332618405 M2P_SUMDATA8__21: 8 MBMU
 SG_ M2P_SysMaxVolt_HvOn_21 : 0|16@1+ (1,0) [0|65535] "mV"  PC
 SG_ M2P_SysMinVolt_HvOn_21 : 16|16@1+ (1,0) [0|65535] "mV"  PC
 SG_ M2P_SysAvgVolt_HvOn_21 : 32|16@1+ (1,0) [0|65535] "mV"  PC

BO_ 2332618406 M2P_SUMDATA8__22: 8 MBMU
 SG_ M2P_SysMaxVolt_HvOn_22 : 0|16@1+ (1,0) [0|65535] "mV"  PC
 SG_ M2P_SysMinVolt_HvOn_22 : 16|16@1+ (1,0) [0|65535] "mV"  PC
 SG_ M2P_SysAvgVolt_HvOn_22 : 32|16@1+ (1,0) [0|65535] "mV"  PC

BO_ 2332618407 M2P_SUMDATA8__23: 8 MBMU
 SG_ M2P_SysMaxVolt_HvOn_23 : 0|16@1+ (1,0) [0|65535] "mV"  PC
 SG_ M2P_SysMinVolt_HvOn_23 : 16|16@1+ (1,0) [0|65535] "mV"  PC
 SG_ M2P_SysAvgVolt_HvOn_23 : 32|16@1+ (1,0) [0|65535] "mV"  PC

BO_ 2332618408 M2P_SUMDATA8__24: 8 MBMU
 SG_ M2P_SysMaxVolt_HvOn_24 : 0|16@1+ (1,0) [0|65535] "mV"  PC
 SG_ M2P_SysMinVolt_HvOn_24 : 16|16@1+ (1,0) [0|65535] "mV"  PC
 SG_ M2P_SysAvgVolt_HvOn_24 : 32|16@1+ (1,0) [0|65535] "mV"  PC

BO_ 2332618409 M2P_SUMDATA8__25: 8 MBMU
 SG_ M2P_SysMaxVolt_HvOn_25 : 0|16@1+ (1,0) [0|65535] "mV"  PC
 SG_ M2P_SysMinVolt_HvOn_25 : 16|16@1+ (1,0) [0|65535] "mV"  PC
 SG_ M2P_SysAvgVolt_HvOn_25 : 32|16@1+ (1,0) [0|65535] "mV"  PC

BO_ 2332618410 M2P_SUMDATA8__26: 8 MBMU
 SG_ M2P_SysMaxVolt_HvOn_26 : 0|16@1+ (1,0) [0|65535] "mV"  PC
 SG_ M2P_SysMinVolt_HvOn_26 : 16|16@1+ (1,0) [0|65535] "mV"  PC
 SG_ M2P_SysAvgVolt_HvOn_26 : 32|16@1+ (1,0) [0|65535] "mV"  PC

BO_ 2332618411 M2P_SUMDATA8__27: 8 MBMU
 SG_ M2P_SysMaxVolt_HvOn_27 : 0|16@1+ (1,0) [0|65535] "mV"  PC
 SG_ M2P_SysMinVolt_HvOn_27 : 16|16@1+ (1,0) [0|65535] "mV"  PC
 SG_ M2P_SysAvgVolt_HvOn_27 : 32|16@1+ (1,0) [0|65535] "mV"  PC

BO_ 2332618412 M2P_SUMDATA8__28: 8 MBMU
 SG_ M2P_SysMaxVolt_HvOn_28 : 0|16@1+ (1,0) [0|65535] "mV"  PC
 SG_ M2P_SysMinVolt_HvOn_28 : 16|16@1+ (1,0) [0|65535] "mV"  PC
 SG_ M2P_SysAvgVolt_HvOn_28 : 32|16@1+ (1,0) [0|65535] "mV"  PC

BO_ 2332618413 M2P_SUMDATA8__29: 8 MBMU
 SG_ M2P_SysMaxVolt_HvOn_29 : 0|16@1+ (1,0) [0|65535] "mV"  PC
 SG_ M2P_SysMinVolt_HvOn_29 : 16|16@1+ (1,0) [0|65535] "mV"  PC
 SG_ M2P_SysAvgVolt_HvOn_29 : 32|16@1+ (1,0) [0|65535] "mV"  PC

BO_ 2332618414 M2P_SUMDATA8__30: 8 MBMU
 SG_ M2P_SysMaxVolt_HvOn_30 : 0|16@1+ (1,0) [0|65535] "mV"  PC
 SG_ M2P_SysMinVolt_HvOn_30 : 16|16@1+ (1,0) [0|65535] "mV"  PC
 SG_ M2P_SysAvgVolt_HvOn_30 : 32|16@1+ (1,0) [0|65535] "mV"  PC

BO_ 2332618415 M2P_SUMDATA8__31: 8 MBMU
 SG_ M2P_SysMaxVolt_HvOn_31 : 0|16@1+ (1,0) [0|65535] "mV"  PC
 SG_ M2P_SysMinVolt_HvOn_31 : 16|16@1+ (1,0) [0|65535] "mV"  PC
 SG_ M2P_SysAvgVolt_HvOn_31 : 32|16@1+ (1,0) [0|65535] "mV"  PC

BO_ 2332683921 M2P_SUMDATA9__01: 8 MBMU
 SG_ M2P_SysMaxTemp_HvOn01 : 0|8@1+ (1,-50) [0|205] "℃"  PC
 SG_ M2P_SysMinTemp_HvOn01 : 8|8@1+ (1,-50) [0|205] "℃"  PC
 SG_ M2P_SysAvgTemp_HvOn01 : 16|8@1+ (1,-50) [0|205] "℃"  PC
 SG_ M2P_SbmuPst_SysMaxTemp_HvOn01 : 24|8@1+ (1,0) [0|255] ""  PC
 SG_ M2P_CscPst_SysMaxTemp_HvOn01 : 32|8@1+ (1,0) [0|255] ""  PC
 SG_ M2P_SbmuPst_SysMinTemp_HvOn01 : 40|8@1+ (1,0) [0|255] ""  PC
 SG_ M2P_CscPst_SysMinTemp_HvOn01 : 48|8@1+ (1,0) [0|255] ""  PC

BO_ 2332683922 M2P_SUMDATA9__02: 8 MBMU
 SG_ M2P_SysMaxTemp_HvOn02 : 0|8@1+ (1,-50) [0|205] "℃"  PC
 SG_ M2P_SysMinTemp_HvOn02 : 8|8@1+ (1,-50) [0|205] "℃"  PC
 SG_ M2P_SysAvgTemp_HvOn02 : 16|8@1+ (1,-50) [0|205] "℃"  PC
 SG_ M2P_SbmuPst_SysMaxTemp_HvOn02 : 24|8@1+ (1,0) [0|255] ""  PC
 SG_ M2P_CscPst_SysMaxTemp_HvOn02 : 32|8@1+ (1,0) [0|255] ""  PC
 SG_ M2P_SbmuPst_SysMinTemp_HvOn02 : 40|8@1+ (1,0) [0|255] ""  PC
 SG_ M2P_CscPst_SysMinTemp_HvOn02 : 48|8@1+ (1,0) [0|255] ""  PC

BO_ 2332683923 M2P_SUMDATA9__03: 8 MBMU
 SG_ M2P_SysMaxTemp_HvOn03 : 0|8@1+ (1,-50) [0|205] "℃"  PC
 SG_ M2P_SysMinTemp_HvOn03 : 8|8@1+ (1,-50) [0|205] "℃"  PC
 SG_ M2P_SysAvgTemp_HvOn03 : 16|8@1+ (1,-50) [0|205] "℃"  PC
 SG_ M2P_SbmuPst_SysMaxTemp_HvOn03 : 24|8@1+ (1,0) [0|255] ""  PC
 SG_ M2P_CscPst_SysMaxTemp_HvOn03 : 32|8@1+ (1,0) [0|255] ""  PC
 SG_ M2P_SbmuPst_SysMinTemp_HvOn03 : 40|8@1+ (1,0) [0|255] ""  PC
 SG_ M2P_CscPst_SysMinTemp_HvOn03 : 48|8@1+ (1,0) [0|255] ""  PC

BO_ 2332683924 M2P_SUMDATA9__04: 8 MBMU
 SG_ M2P_SysMaxTemp_HvOn04 : 0|8@1+ (1,-50) [0|205] "℃"  PC
 SG_ M2P_SysMinTemp_HvOn04 : 8|8@1+ (1,-50) [0|205] "℃"  PC
 SG_ M2P_SysAvgTemp_HvOn04 : 16|8@1+ (1,-50) [0|205] "℃"  PC
 SG_ M2P_SbmuPst_SysMaxTemp_HvOn04 : 24|8@1+ (1,0) [0|255] ""  PC
 SG_ M2P_CscPst_SysMaxTemp_HvOn04 : 32|8@1+ (1,0) [0|255] ""  PC
 SG_ M2P_SbmuPst_SysMinTemp_HvOn04 : 40|8@1+ (1,0) [0|255] ""  PC
 SG_ M2P_CscPst_SysMinTemp_HvOn04 : 48|8@1+ (1,0) [0|255] ""  PC

BO_ 2332683925 M2P_SUMDATA9__05: 8 MBMU
 SG_ M2P_SysMaxTemp_HvOn05 : 0|8@1+ (1,-50) [0|205] "℃"  PC
 SG_ M2P_SysMinTemp_HvOn05 : 8|8@1+ (1,-50) [0|205] "℃"  PC
 SG_ M2P_SysAvgTemp_HvOn05 : 16|8@1+ (1,-50) [0|205] "℃"  PC
 SG_ M2P_SbmuPst_SysMaxTemp_HvOn05 : 24|8@1+ (1,0) [0|255] ""  PC
 SG_ M2P_CscPst_SysMaxTemp_HvOn05 : 32|8@1+ (1,0) [0|255] ""  PC
 SG_ M2P_SbmuPst_SysMinTemp_HvOn05 : 40|8@1+ (1,0) [0|255] ""  PC
 SG_ M2P_CscPst_SysMinTemp_HvOn05 : 48|8@1+ (1,0) [0|255] ""  PC

BO_ 2332683926 M2P_SUMDATA9__06: 8 MBMU
 SG_ M2P_SysMaxTemp_HvOn06 : 0|8@1+ (1,-50) [0|205] "℃"  PC
 SG_ M2P_SysMinTemp_HvOn06 : 8|8@1+ (1,-50) [0|205] "℃"  PC
 SG_ M2P_SysAvgTemp_HvOn06 : 16|8@1+ (1,-50) [0|205] "℃"  PC
 SG_ M2P_SbmuPst_SysMaxTemp_HvOn06 : 24|8@1+ (1,0) [0|255] ""  PC
 SG_ M2P_CscPst_SysMaxTemp_HvOn06 : 32|8@1+ (1,0) [0|255] ""  PC
 SG_ M2P_SbmuPst_SysMinTemp_HvOn06 : 40|8@1+ (1,0) [0|255] ""  PC
 SG_ M2P_CscPst_SysMinTemp_HvOn06 : 48|8@1+ (1,0) [0|255] ""  PC

BO_ 2332683927 M2P_SUMDATA9__07: 8 MBMU
 SG_ M2P_SysMaxTemp_HvOn07 : 0|8@1+ (1,-50) [0|205] "℃"  PC
 SG_ M2P_SysMinTemp_HvOn07 : 8|8@1+ (1,-50) [0|205] "℃"  PC
 SG_ M2P_SysAvgTemp_HvOn07 : 16|8@1+ (1,-50) [0|205] "℃"  PC
 SG_ M2P_SbmuPst_SysMaxTemp_HvOn07 : 24|8@1+ (1,0) [0|255] ""  PC
 SG_ M2P_CscPst_SysMaxTemp_HvOn07 : 32|8@1+ (1,0) [0|255] ""  PC
 SG_ M2P_SbmuPst_SysMinTemp_HvOn07 : 40|8@1+ (1,0) [0|255] ""  PC
 SG_ M2P_CscPst_SysMinTemp_HvOn07 : 48|8@1+ (1,0) [0|255] ""  PC

BO_ 2332683928 M2P_SUMDATA9__08: 8 MBMU
 SG_ M2P_SysMaxTemp_HvOn08 : 0|8@1+ (1,-50) [0|205] "℃"  PC
 SG_ M2P_SysMinTemp_HvOn08 : 8|8@1+ (1,-50) [0|205] "℃"  PC
 SG_ M2P_SysAvgTemp_HvOn08 : 16|8@1+ (1,-50) [0|205] "℃"  PC
 SG_ M2P_SbmuPst_SysMaxTemp_HvOn08 : 24|8@1+ (1,0) [0|255] ""  PC
 SG_ M2P_CscPst_SysMaxTemp_HvOn08 : 32|8@1+ (1,0) [0|255] ""  PC
 SG_ M2P_SbmuPst_SysMinTemp_HvOn08 : 40|8@1+ (1,0) [0|255] ""  PC
 SG_ M2P_CscPst_SysMinTemp_HvOn08 : 48|8@1+ (1,0) [0|255] ""  PC

BO_ 2332683929 M2P_SUMDATA9__09: 8 MBMU
 SG_ M2P_SysMaxTemp_HvOn09 : 0|8@1+ (1,-50) [0|205] "℃"  PC
 SG_ M2P_SysMinTemp_HvOn09 : 8|8@1+ (1,-50) [0|205] "℃"  PC
 SG_ M2P_SysAvgTemp_HvOn09 : 16|8@1+ (1,-50) [0|205] "℃"  PC
 SG_ M2P_SbmuPst_SysMaxTemp_HvOn09 : 24|8@1+ (1,0) [0|255] ""  PC
 SG_ M2P_CscPst_SysMaxTemp_HvOn09 : 32|8@1+ (1,0) [0|255] ""  PC
 SG_ M2P_SbmuPst_SysMinTemp_HvOn09 : 40|8@1+ (1,0) [0|255] ""  PC
 SG_ M2P_CscPst_SysMinTemp_HvOn09 : 48|8@1+ (1,0) [0|255] ""  PC

BO_ 2332683930 M2P_SUMDATA9__10: 8 MBMU
 SG_ M2P_SysMaxTemp_HvOn10 : 0|8@1+ (1,-50) [0|205] "℃"  PC
 SG_ M2P_SysMinTemp_HvOn10 : 8|8@1+ (1,-50) [0|205] "℃"  PC
 SG_ M2P_SysAvgTemp_HvOn10 : 16|8@1+ (1,-50) [0|205] "℃"  PC
 SG_ M2P_SbmuPst_SysMaxTemp_HvOn10 : 24|8@1+ (1,0) [0|255] ""  PC
 SG_ M2P_CscPst_SysMaxTemp_HvOn10 : 32|8@1+ (1,0) [0|255] ""  PC
 SG_ M2P_SbmuPst_SysMinTemp_HvOn10 : 40|8@1+ (1,0) [0|255] ""  PC
 SG_ M2P_CscPst_SysMinTemp_HvOn10 : 48|8@1+ (1,0) [0|255] ""  PC

BO_ 2332683931 M2P_SUMDATA9__11: 8 MBMU
 SG_ M2P_SysMaxTemp_HvOn11 : 0|8@1+ (1,-50) [0|205] "℃"  PC
 SG_ M2P_SysMinTemp_HvOn11 : 8|8@1+ (1,-50) [0|205] "℃"  PC
 SG_ M2P_SysAvgTemp_HvOn11 : 16|8@1+ (1,-50) [0|205] "℃"  PC
 SG_ M2P_SbmuPst_SysMaxTemp_HvOn11 : 24|8@1+ (1,0) [0|255] ""  PC
 SG_ M2P_CscPst_SysMaxTemp_HvOn11 : 32|8@1+ (1,0) [0|255] ""  PC
 SG_ M2P_SbmuPst_SysMinTemp_HvOn11 : 40|8@1+ (1,0) [0|255] ""  PC
 SG_ M2P_CscPst_SysMinTemp_HvOn11 : 48|8@1+ (1,0) [0|255] ""  PC

BO_ 2332683932 M2P_SUMDATA9__12: 8 MBMU
 SG_ M2P_SysMaxTemp_HvOn12 : 0|8@1+ (1,-50) [0|205] "℃"  PC
 SG_ M2P_SysMinTemp_HvOn12 : 8|8@1+ (1,-50) [0|205] "℃"  PC
 SG_ M2P_SysAvgTemp_HvOn12 : 16|8@1+ (1,-50) [0|205] "℃"  PC
 SG_ M2P_SbmuPst_SysMaxTemp_HvOn12 : 24|8@1+ (1,0) [0|255] ""  PC
 SG_ M2P_CscPst_SysMaxTemp_HvOn12 : 32|8@1+ (1,0) [0|255] ""  PC
 SG_ M2P_SbmuPst_SysMinTemp_HvOn12 : 40|8@1+ (1,0) [0|255] ""  PC
 SG_ M2P_CscPst_SysMinTemp_HvOn12 : 48|8@1+ (1,0) [0|255] ""  PC

BO_ 2332683933 M2P_SUMDATA9__13: 8 MBMU
 SG_ M2P_SysMaxTemp_HvOn13 : 0|8@1+ (1,-50) [0|205] "℃"  PC
 SG_ M2P_SysMinTemp_HvOn13 : 8|8@1+ (1,-50) [0|205] "℃"  PC
 SG_ M2P_SysAvgTemp_HvOn13 : 16|8@1+ (1,-50) [0|205] "℃"  PC
 SG_ M2P_SbmuPst_SysMaxTemp_HvOn13 : 24|8@1+ (1,0) [0|255] ""  PC
 SG_ M2P_CscPst_SysMaxTemp_HvOn13 : 32|8@1+ (1,0) [0|255] ""  PC
 SG_ M2P_SbmuPst_SysMinTemp_HvOn13 : 40|8@1+ (1,0) [0|255] ""  PC
 SG_ M2P_CscPst_SysMinTemp_HvOn13 : 48|8@1+ (1,0) [0|255] ""  PC

BO_ 2332683934 M2P_SUMDATA9__14: 8 MBMU
 SG_ M2P_SysMaxTemp_HvOn14 : 0|8@1+ (1,-50) [0|205] "℃"  PC
 SG_ M2P_SysMinTemp_HvOn14 : 8|8@1+ (1,-50) [0|205] "℃"  PC
 SG_ M2P_SysAvgTemp_HvOn14 : 16|8@1+ (1,-50) [0|205] "℃"  PC
 SG_ M2P_SbmuPst_SysMaxTemp_HvOn14 : 24|8@1+ (1,0) [0|255] ""  PC
 SG_ M2P_CscPst_SysMaxTemp_HvOn14 : 32|8@1+ (1,0) [0|255] ""  PC
 SG_ M2P_SbmuPst_SysMinTemp_HvOn14 : 40|8@1+ (1,0) [0|255] ""  PC
 SG_ M2P_CscPst_SysMinTemp_HvOn14 : 48|8@1+ (1,0) [0|255] ""  PC

BO_ 2332683935 M2P_SUMDATA9__15: 8 MBMU
 SG_ M2P_SysMaxTemp_HvOn15 : 0|8@1+ (1,-50) [0|205] "℃"  PC
 SG_ M2P_SysMinTemp_HvOn15 : 8|8@1+ (1,-50) [0|205] "℃"  PC
 SG_ M2P_SysAvgTemp_HvOn15 : 16|8@1+ (1,-50) [0|205] "℃"  PC
 SG_ M2P_SbmuPst_SysMaxTemp_HvOn15 : 24|8@1+ (1,0) [0|255] ""  PC
 SG_ M2P_CscPst_SysMaxTemp_HvOn15 : 32|8@1+ (1,0) [0|255] ""  PC
 SG_ M2P_SbmuPst_SysMinTemp_HvOn15 : 40|8@1+ (1,0) [0|255] ""  PC
 SG_ M2P_CscPst_SysMinTemp_HvOn15 : 48|8@1+ (1,0) [0|255] ""  PC

BO_ 2332683936 M2P_SUMDATA9__16: 8 MBMU
 SG_ M2P_SysMaxTemp_HvOn16 : 0|8@1+ (1,-50) [0|205] "℃"  PC
 SG_ M2P_SysMinTemp_HvOn16 : 8|8@1+ (1,-50) [0|205] "℃"  PC
 SG_ M2P_SysAvgTemp_HvOn16 : 16|8@1+ (1,-50) [0|205] "℃"  PC
 SG_ M2P_SbmuPst_SysMaxTemp_HvOn16 : 24|8@1+ (1,0) [0|255] ""  PC
 SG_ M2P_CscPst_SysMaxTemp_HvOn16 : 32|8@1+ (1,0) [0|255] ""  PC
 SG_ M2P_SbmuPst_SysMinTemp_HvOn16 : 40|8@1+ (1,0) [0|255] ""  PC
 SG_ M2P_CscPst_SysMinTemp_HvOn16 : 48|8@1+ (1,0) [0|255] ""  PC

BO_ 2332683937 M2P_SUMDATA9__17: 8 MBMU
 SG_ M2P_SysMaxTemp_HvOn17 : 0|8@1+ (1,-50) [0|205] "℃"  PC
 SG_ M2P_SysMinTemp_HvOn17 : 8|8@1+ (1,-50) [0|205] "℃"  PC
 SG_ M2P_SysAvgTemp_HvOn17 : 16|8@1+ (1,-50) [0|205] "℃"  PC
 SG_ M2P_SbmuPst_SysMaxTemp_HvOn17 : 24|8@1+ (1,0) [0|255] ""  PC
 SG_ M2P_CscPst_SysMaxTemp_HvOn17 : 32|8@1+ (1,0) [0|255] ""  PC
 SG_ M2P_SbmuPst_SysMinTemp_HvOn17 : 40|8@1+ (1,0) [0|255] ""  PC
 SG_ M2P_CscPst_SysMinTemp_HvOn17 : 48|8@1+ (1,0) [0|255] ""  PC

BO_ 2332683938 M2P_SUMDATA9__18: 8 MBMU
 SG_ M2P_SysMaxTemp_HvOn18 : 0|8@1+ (1,-50) [0|205] "℃"  PC
 SG_ M2P_SysMinTemp_HvOn18 : 8|8@1+ (1,-50) [0|205] "℃"  PC
 SG_ M2P_SysAvgTemp_HvOn18 : 16|8@1+ (1,-50) [0|205] "℃"  PC
 SG_ M2P_SbmuPst_SysMaxTemp_HvOn18 : 24|8@1+ (1,0) [0|255] ""  PC
 SG_ M2P_CscPst_SysMaxTemp_HvOn18 : 32|8@1+ (1,0) [0|255] ""  PC
 SG_ M2P_SbmuPst_SysMinTemp_HvOn18 : 40|8@1+ (1,0) [0|255] ""  PC
 SG_ M2P_CscPst_SysMinTemp_HvOn18 : 48|8@1+ (1,0) [0|255] ""  PC

BO_ 2332683939 M2P_SUMDATA9__19: 8 MBMU
 SG_ M2P_SysMaxTemp_HvOn19 : 0|8@1+ (1,-50) [0|205] "℃"  PC
 SG_ M2P_SysMinTemp_HvOn19 : 8|8@1+ (1,-50) [0|205] "℃"  PC
 SG_ M2P_SysAvgTemp_HvOn19 : 16|8@1+ (1,-50) [0|205] "℃"  PC
 SG_ M2P_SbmuPst_SysMaxTemp_HvOn19 : 24|8@1+ (1,0) [0|255] ""  PC
 SG_ M2P_CscPst_SysMaxTemp_HvOn19 : 32|8@1+ (1,0) [0|255] ""  PC
 SG_ M2P_SbmuPst_SysMinTemp_HvOn19 : 40|8@1+ (1,0) [0|255] ""  PC
 SG_ M2P_CscPst_SysMinTemp_HvOn19 : 48|8@1+ (1,0) [0|255] ""  PC

BO_ 2332683940 M2P_SUMDATA9__20: 8 MBMU
 SG_ M2P_SysMaxTemp_HvOn20 : 0|8@1+ (1,-50) [0|205] "℃"  PC
 SG_ M2P_SysMinTemp_HvOn20 : 8|8@1+ (1,-50) [0|205] "℃"  PC
 SG_ M2P_SysAvgTemp_HvOn20 : 16|8@1+ (1,-50) [0|205] "℃"  PC
 SG_ M2P_SbmuPst_SysMaxTemp_HvOn20 : 24|8@1+ (1,0) [0|255] ""  PC
 SG_ M2P_CscPst_SysMaxTemp_HvOn20 : 32|8@1+ (1,0) [0|255] ""  PC
 SG_ M2P_SbmuPst_SysMinTemp_HvOn20 : 40|8@1+ (1,0) [0|255] ""  PC
 SG_ M2P_CscPst_SysMinTemp_HvOn20 : 48|8@1+ (1,0) [0|255] ""  PC

BO_ 2332683941 M2P_SUMDATA9__21: 8 MBMU
 SG_ M2P_SysMaxTemp_HvOn21 : 0|8@1+ (1,-50) [0|205] "℃"  PC
 SG_ M2P_SysMinTemp_HvOn21 : 8|8@1+ (1,-50) [0|205] "℃"  PC
 SG_ M2P_SysAvgTemp_HvOn21 : 16|8@1+ (1,-50) [0|205] "℃"  PC
 SG_ M2P_SbmuPst_SysMaxTemp_HvOn21 : 24|8@1+ (1,0) [0|255] ""  PC
 SG_ M2P_CscPst_SysMaxTemp_HvOn21 : 32|8@1+ (1,0) [0|255] ""  PC
 SG_ M2P_SbmuPst_SysMinTemp_HvOn21 : 40|8@1+ (1,0) [0|255] ""  PC
 SG_ M2P_CscPst_SysMinTemp_HvOn21 : 48|8@1+ (1,0) [0|255] ""  PC

BO_ 2332683942 M2P_SUMDATA9__22: 8 MBMU
 SG_ M2P_SysMaxTemp_HvOn22 : 0|8@1+ (1,-50) [0|205] "℃"  PC
 SG_ M2P_SysMinTemp_HvOn22 : 8|8@1+ (1,-50) [0|205] "℃"  PC
 SG_ M2P_SysAvgTemp_HvOn22 : 16|8@1+ (1,-50) [0|205] "℃"  PC
 SG_ M2P_SbmuPst_SysMaxTemp_HvOn22 : 24|8@1+ (1,0) [0|255] ""  PC
 SG_ M2P_CscPst_SysMaxTemp_HvOn22 : 32|8@1+ (1,0) [0|255] ""  PC
 SG_ M2P_SbmuPst_SysMinTemp_HvOn22 : 40|8@1+ (1,0) [0|255] ""  PC
 SG_ M2P_CscPst_SysMinTemp_HvOn22 : 48|8@1+ (1,0) [0|255] ""  PC

BO_ 2332683943 M2P_SUMDATA9__23: 8 MBMU
 SG_ M2P_SysMaxTemp_HvOn23 : 0|8@1+ (1,-50) [0|205] "℃"  PC
 SG_ M2P_SysMinTemp_HvOn23 : 8|8@1+ (1,-50) [0|205] "℃"  PC
 SG_ M2P_SysAvgTemp_HvOn23 : 16|8@1+ (1,-50) [0|205] "℃"  PC
 SG_ M2P_SbmuPst_SysMaxTemp_HvOn23 : 24|8@1+ (1,0) [0|255] ""  PC
 SG_ M2P_CscPst_SysMaxTemp_HvOn23 : 32|8@1+ (1,0) [0|255] ""  PC
 SG_ M2P_SbmuPst_SysMinTemp_HvOn23 : 40|8@1+ (1,0) [0|255] ""  PC
 SG_ M2P_CscPst_SysMinTemp_HvOn23 : 48|8@1+ (1,0) [0|255] ""  PC

BO_ 2332683944 M2P_SUMDATA9__24: 8 MBMU
 SG_ M2P_SysMaxTemp_HvOn24 : 0|8@1+ (1,-50) [0|205] "℃"  PC
 SG_ M2P_SysMinTemp_HvOn24 : 8|8@1+ (1,-50) [0|205] "℃"  PC
 SG_ M2P_SysAvgTemp_HvOn24 : 16|8@1+ (1,-50) [0|205] "℃"  PC
 SG_ M2P_SbmuPst_SysMaxTemp_HvOn24 : 24|8@1+ (1,0) [0|255] ""  PC
 SG_ M2P_CscPst_SysMaxTemp_HvOn24 : 32|8@1+ (1,0) [0|255] ""  PC
 SG_ M2P_SbmuPst_SysMinTemp_HvOn24 : 40|8@1+ (1,0) [0|255] ""  PC
 SG_ M2P_CscPst_SysMinTemp_HvOn24 : 48|8@1+ (1,0) [0|255] ""  PC

BO_ 2332683945 M2P_SUMDATA9__25: 8 MBMU
 SG_ M2P_SysMaxTemp_HvOn25 : 0|8@1+ (1,-50) [0|205] "℃"  PC
 SG_ M2P_SysMinTemp_HvOn25 : 8|8@1+ (1,-50) [0|205] "℃"  PC
 SG_ M2P_SysAvgTemp_HvOn25 : 16|8@1+ (1,-50) [0|205] "℃"  PC
 SG_ M2P_SbmuPst_SysMaxTemp_HvOn25 : 24|8@1+ (1,0) [0|255] ""  PC
 SG_ M2P_CscPst_SysMaxTemp_HvOn25 : 32|8@1+ (1,0) [0|255] ""  PC
 SG_ M2P_SbmuPst_SysMinTemp_HvOn25 : 40|8@1+ (1,0) [0|255] ""  PC
 SG_ M2P_CscPst_SysMinTemp_HvOn25 : 48|8@1+ (1,0) [0|255] ""  PC

BO_ 2332683946 M2P_SUMDATA9__26: 8 MBMU
 SG_ M2P_SysMaxTemp_HvOn26 : 0|8@1+ (1,-50) [0|205] "℃"  PC
 SG_ M2P_SysMinTemp_HvOn26 : 8|8@1+ (1,-50) [0|205] "℃"  PC
 SG_ M2P_SysAvgTemp_HvOn26 : 16|8@1+ (1,-50) [0|205] "℃"  PC
 SG_ M2P_SbmuPst_SysMaxTemp_HvOn26 : 24|8@1+ (1,0) [0|255] ""  PC
 SG_ M2P_CscPst_SysMaxTemp_HvOn26 : 32|8@1+ (1,0) [0|255] ""  PC
 SG_ M2P_SbmuPst_SysMinTemp_HvOn26 : 40|8@1+ (1,0) [0|255] ""  PC
 SG_ M2P_CscPst_SysMinTemp_HvOn26 : 48|8@1+ (1,0) [0|255] ""  PC

BO_ 2332683947 M2P_SUMDATA9__27: 8 MBMU
 SG_ M2P_SysMaxTemp_HvOn27 : 0|8@1+ (1,-50) [0|205] "℃"  PC
 SG_ M2P_SysMinTemp_HvOn27 : 8|8@1+ (1,-50) [0|205] "℃"  PC
 SG_ M2P_SysAvgTemp_HvOn27 : 16|8@1+ (1,-50) [0|205] "℃"  PC
 SG_ M2P_SbmuPst_SysMaxTemp_HvOn27 : 24|8@1+ (1,0) [0|255] ""  PC
 SG_ M2P_CscPst_SysMaxTemp_HvOn27 : 32|8@1+ (1,0) [0|255] ""  PC
 SG_ M2P_SbmuPst_SysMinTemp_HvOn27 : 40|8@1+ (1,0) [0|255] ""  PC
 SG_ M2P_CscPst_SysMinTemp_HvOn27 : 48|8@1+ (1,0) [0|255] ""  PC

BO_ 2332683948 M2P_SUMDATA9__28: 8 MBMU
 SG_ M2P_SysMaxTemp_HvOn28 : 0|8@1+ (1,-50) [0|205] "℃"  PC
 SG_ M2P_SysMinTemp_HvOn28 : 8|8@1+ (1,-50) [0|205] "℃"  PC
 SG_ M2P_SysAvgTemp_HvOn28 : 16|8@1+ (1,-50) [0|205] "℃"  PC
 SG_ M2P_SbmuPst_SysMaxTemp_HvOn28 : 24|8@1+ (1,0) [0|255] ""  PC
 SG_ M2P_CscPst_SysMaxTemp_HvOn28 : 32|8@1+ (1,0) [0|255] ""  PC
 SG_ M2P_SbmuPst_SysMinTemp_HvOn28 : 40|8@1+ (1,0) [0|255] ""  PC
 SG_ M2P_CscPst_SysMinTemp_HvOn28 : 48|8@1+ (1,0) [0|255] ""  PC

CM_ SG_ 2483416743 E2P_Cfg3_HW_Ver_Byte1 "ETH硬件版本字节1";
CM_ SG_ 2483416743 E2P_Cfg3_HW_Ver_Byte2 "ETH硬件版本字节2";
CM_ SG_ 2483416743 E2P_Cfg3_HW_Ver_Byte3 "ETH硬件版本字节3";
CM_ SG_ 2483416743 E2P_Cfg3_HW_Ver_Byte4 "ETH硬件版本字节4";
CM_ SG_ 2483416743 E2P_Cfg3_HW_Ver_Byte5 "ETH硬件版本字节5";
CM_ SG_ 2483416743 E2P_Cfg3_HW_Ver_Byte6 "ETH硬件版本字节6";
CM_ SG_ 2483416743 E2P_Cfg3_HW_Ver_Byte7 "ETH硬件版本字节7";
CM_ SG_ 2483416743 E2P_Cfg3_HW_Ver_Byte8 "ETH硬件版本字节8";
CM_ SG_ 2483416744 E2P_Cfg3_HW_Ver_Byte1 "ETH硬件版本字节1";
CM_ SG_ 2483416744 E2P_Cfg3_HW_Ver_Byte2 "ETH硬件版本字节2";
CM_ SG_ 2483416744 E2P_Cfg3_HW_Ver_Byte3 "ETH硬件版本字节3";
CM_ SG_ 2483416744 E2P_Cfg3_HW_Ver_Byte4 "ETH硬件版本字节4";
CM_ SG_ 2483416744 E2P_Cfg3_HW_Ver_Byte5 "ETH硬件版本字节5";
CM_ SG_ 2483416744 E2P_Cfg3_HW_Ver_Byte6 "ETH硬件版本字节6";
CM_ SG_ 2483416744 E2P_Cfg3_HW_Ver_Byte7 "ETH硬件版本字节7";
CM_ SG_ 2483416744 E2P_Cfg3_HW_Ver_Byte8 "ETH硬件版本字节8";
CM_ SG_ 2483416745 E2P_Cfg3_HW_Ver_Byte1 "ETH硬件版本字节1";
CM_ SG_ 2483416745 E2P_Cfg3_HW_Ver_Byte2 "ETH硬件版本字节2";
CM_ SG_ 2483416745 E2P_Cfg3_HW_Ver_Byte3 "ETH硬件版本字节3";
CM_ SG_ 2483416745 E2P_Cfg3_HW_Ver_Byte4 "ETH硬件版本字节4";
CM_ SG_ 2483416745 E2P_Cfg3_HW_Ver_Byte5 "ETH硬件版本字节5";
CM_ SG_ 2483416745 E2P_Cfg3_HW_Ver_Byte6 "ETH硬件版本字节6";
CM_ SG_ 2483416745 E2P_Cfg3_HW_Ver_Byte7 "ETH硬件版本字节7";
CM_ SG_ 2483416745 E2P_Cfg3_HW_Ver_Byte8 "ETH硬件版本字节8";
CM_ SG_ 2483416746 E2P_Cfg3_HW_Ver_Byte1 "ETH硬件版本字节1";
CM_ SG_ 2483416746 E2P_Cfg3_HW_Ver_Byte2 "ETH硬件版本字节2";
CM_ SG_ 2483416746 E2P_Cfg3_HW_Ver_Byte3 "ETH硬件版本字节3";
CM_ SG_ 2483416746 E2P_Cfg3_HW_Ver_Byte4 "ETH硬件版本字节4";
CM_ SG_ 2483416746 E2P_Cfg3_HW_Ver_Byte5 "ETH硬件版本字节5";
CM_ SG_ 2483416746 E2P_Cfg3_HW_Ver_Byte6 "ETH硬件版本字节6";
CM_ SG_ 2483416746 E2P_Cfg3_HW_Ver_Byte7 "ETH硬件版本字节7";
CM_ SG_ 2483416746 E2P_Cfg3_HW_Ver_Byte8 "ETH硬件版本字节8";
CM_ SG_ 2483416747 E2P_Cfg3_HW_Ver_Byte1 "ETH硬件版本字节1";
CM_ SG_ 2483416747 E2P_Cfg3_HW_Ver_Byte2 "ETH硬件版本字节2";
CM_ SG_ 2483416747 E2P_Cfg3_HW_Ver_Byte3 "ETH硬件版本字节3";
CM_ SG_ 2483416747 E2P_Cfg3_HW_Ver_Byte4 "ETH硬件版本字节4";
CM_ SG_ 2483416747 E2P_Cfg3_HW_Ver_Byte5 "ETH硬件版本字节5";
CM_ SG_ 2483416747 E2P_Cfg3_HW_Ver_Byte6 "ETH硬件版本字节6";
CM_ SG_ 2483416747 E2P_Cfg3_HW_Ver_Byte7 "ETH硬件版本字节7";
CM_ SG_ 2483416747 E2P_Cfg3_HW_Ver_Byte8 "ETH硬件版本字节8";
CM_ SG_ 2483416748 E2P_Cfg3_HW_Ver_Byte1 "ETH硬件版本字节1";
CM_ SG_ 2483416748 E2P_Cfg3_HW_Ver_Byte2 "ETH硬件版本字节2";
CM_ SG_ 2483416748 E2P_Cfg3_HW_Ver_Byte3 "ETH硬件版本字节3";
CM_ SG_ 2483416748 E2P_Cfg3_HW_Ver_Byte4 "ETH硬件版本字节4";
CM_ SG_ 2483416748 E2P_Cfg3_HW_Ver_Byte5 "ETH硬件版本字节5";
CM_ SG_ 2483416748 E2P_Cfg3_HW_Ver_Byte6 "ETH硬件版本字节6";
CM_ SG_ 2483416748 E2P_Cfg3_HW_Ver_Byte7 "ETH硬件版本字节7";
CM_ SG_ 2483416748 E2P_Cfg3_HW_Ver_Byte8 "ETH硬件版本字节8";
CM_ SG_ 2483416749 E2P_Cfg3_HW_Ver_Byte1 "ETH硬件版本字节1";
CM_ SG_ 2483416749 E2P_Cfg3_HW_Ver_Byte2 "ETH硬件版本字节2";
CM_ SG_ 2483416749 E2P_Cfg3_HW_Ver_Byte3 "ETH硬件版本字节3";
CM_ SG_ 2483416749 E2P_Cfg3_HW_Ver_Byte4 "ETH硬件版本字节4";
CM_ SG_ 2483416749 E2P_Cfg3_HW_Ver_Byte5 "ETH硬件版本字节5";
CM_ SG_ 2483416749 E2P_Cfg3_HW_Ver_Byte6 "ETH硬件版本字节6";
CM_ SG_ 2483416749 E2P_Cfg3_HW_Ver_Byte7 "ETH硬件版本字节7";
CM_ SG_ 2483416749 E2P_Cfg3_HW_Ver_Byte8 "ETH硬件版本字节8";
CM_ SG_ 2483416750 E2P_Cfg3_HW_Ver_Byte1 "ETH硬件版本字节1";
CM_ SG_ 2483416750 E2P_Cfg3_HW_Ver_Byte2 "ETH硬件版本字节2";
CM_ SG_ 2483416750 E2P_Cfg3_HW_Ver_Byte3 "ETH硬件版本字节3";
CM_ SG_ 2483416750 E2P_Cfg3_HW_Ver_Byte4 "ETH硬件版本字节4";
CM_ SG_ 2483416750 E2P_Cfg3_HW_Ver_Byte5 "ETH硬件版本字节5";
CM_ SG_ 2483416750 E2P_Cfg3_HW_Ver_Byte6 "ETH硬件版本字节6";
CM_ SG_ 2483416750 E2P_Cfg3_HW_Ver_Byte7 "ETH硬件版本字节7";
CM_ SG_ 2483416750 E2P_Cfg3_HW_Ver_Byte8 "ETH硬件版本字节8";
CM_ SG_ 2483416751 E2P_Cfg3_HW_Ver_Byte1 "ETH硬件版本字节1";
CM_ SG_ 2483416751 E2P_Cfg3_HW_Ver_Byte2 "ETH硬件版本字节2";
CM_ SG_ 2483416751 E2P_Cfg3_HW_Ver_Byte3 "ETH硬件版本字节3";
CM_ SG_ 2483416751 E2P_Cfg3_HW_Ver_Byte4 "ETH硬件版本字节4";
CM_ SG_ 2483416751 E2P_Cfg3_HW_Ver_Byte5 "ETH硬件版本字节5";
CM_ SG_ 2483416751 E2P_Cfg3_HW_Ver_Byte6 "ETH硬件版本字节6";
CM_ SG_ 2483416751 E2P_Cfg3_HW_Ver_Byte7 "ETH硬件版本字节7";
CM_ SG_ 2483416751 E2P_Cfg3_HW_Ver_Byte8 "ETH硬件版本字节8";
CM_ SG_ 2483482257 E2P_Cfg4_HW_Ver_Byte9 "ETH硬件版本字节9";
CM_ SG_ 2483482257 E2P_Cfg4_HW_Ver_Byte10 "ETH硬件版本字节10";
CM_ SG_ 2483482257 E2P_Cfg4_HW_Ver_Byte11 "ETH硬件版本字节11";
CM_ SG_ 2483482257 E2P_Cfg4_HW_Ver_Byte12 "ETH硬件版本字节12";
CM_ SG_ 2483482257 E2P_Cfg4_HW_Ver_Byte13 "ETH硬件版本字节13";
CM_ SG_ 2483482257 E2P_Cfg4_HW_Ver_Byte14 "ETH硬件版本字节14";
CM_ SG_ 2483482257 E2P_Cfg4_HW_Ver_Byte15 "ETH硬件版本字节15";
CM_ SG_ 2483482257 E2P_Cfg4_HW_Ver_Byte16 "ETH硬件版本字节16";
CM_ SG_ 2483482258 E2P_Cfg4_HW_Ver_Byte9 "ETH硬件版本字节9";
CM_ SG_ 2483482258 E2P_Cfg4_HW_Ver_Byte10 "ETH硬件版本字节10";
CM_ SG_ 2483482258 E2P_Cfg4_HW_Ver_Byte11 "ETH硬件版本字节11";
CM_ SG_ 2483482258 E2P_Cfg4_HW_Ver_Byte12 "ETH硬件版本字节12";
CM_ SG_ 2483482258 E2P_Cfg4_HW_Ver_Byte13 "ETH硬件版本字节13";
CM_ SG_ 2483482258 E2P_Cfg4_HW_Ver_Byte14 "ETH硬件版本字节14";
CM_ SG_ 2483482258 E2P_Cfg4_HW_Ver_Byte15 "ETH硬件版本字节15";
CM_ SG_ 2483482258 E2P_Cfg4_HW_Ver_Byte16 "ETH硬件版本字节16";
CM_ SG_ 2483482259 E2P_Cfg4_HW_Ver_Byte9 "ETH硬件版本字节9";
CM_ SG_ 2483482259 E2P_Cfg4_HW_Ver_Byte10 "ETH硬件版本字节10";
CM_ SG_ 2483482259 E2P_Cfg4_HW_Ver_Byte11 "ETH硬件版本字节11";
CM_ SG_ 2483482259 E2P_Cfg4_HW_Ver_Byte12 "ETH硬件版本字节12";
CM_ SG_ 2483482259 E2P_Cfg4_HW_Ver_Byte13 "ETH硬件版本字节13";
CM_ SG_ 2483482259 E2P_Cfg4_HW_Ver_Byte14 "ETH硬件版本字节14";
CM_ SG_ 2483482259 E2P_Cfg4_HW_Ver_Byte15 "ETH硬件版本字节15";
CM_ SG_ 2483482259 E2P_Cfg4_HW_Ver_Byte16 "ETH硬件版本字节16";
CM_ SG_ 2483482260 E2P_Cfg4_HW_Ver_Byte9 "ETH硬件版本字节9";
CM_ SG_ 2483482260 E2P_Cfg4_HW_Ver_Byte10 "ETH硬件版本字节10";
CM_ SG_ 2483482260 E2P_Cfg4_HW_Ver_Byte11 "ETH硬件版本字节11";
CM_ SG_ 2483482260 E2P_Cfg4_HW_Ver_Byte12 "ETH硬件版本字节12";
CM_ SG_ 2483482260 E2P_Cfg4_HW_Ver_Byte13 "ETH硬件版本字节13";
CM_ SG_ 2483482260 E2P_Cfg4_HW_Ver_Byte14 "ETH硬件版本字节14";
CM_ SG_ 2483482260 E2P_Cfg4_HW_Ver_Byte15 "ETH硬件版本字节15";
CM_ SG_ 2483482260 E2P_Cfg4_HW_Ver_Byte16 "ETH硬件版本字节16";
CM_ SG_ 2483482261 E2P_Cfg4_HW_Ver_Byte9 "ETH硬件版本字节9";
CM_ SG_ 2483482261 E2P_Cfg4_HW_Ver_Byte10 "ETH硬件版本字节10";
CM_ SG_ 2483482261 E2P_Cfg4_HW_Ver_Byte11 "ETH硬件版本字节11";
CM_ SG_ 2483482261 E2P_Cfg4_HW_Ver_Byte12 "ETH硬件版本字节12";
CM_ SG_ 2483482261 E2P_Cfg4_HW_Ver_Byte13 "ETH硬件版本字节13";
CM_ SG_ 2483482261 E2P_Cfg4_HW_Ver_Byte14 "ETH硬件版本字节14";
CM_ SG_ 2483482261 E2P_Cfg4_HW_Ver_Byte15 "ETH硬件版本字节15";
CM_ SG_ 2483482261 E2P_Cfg4_HW_Ver_Byte16 "ETH硬件版本字节16";
CM_ SG_ 2483482262 E2P_Cfg4_HW_Ver_Byte9 "ETH硬件版本字节9";
CM_ SG_ 2483482262 E2P_Cfg4_HW_Ver_Byte10 "ETH硬件版本字节10";
CM_ SG_ 2483482262 E2P_Cfg4_HW_Ver_Byte11 "ETH硬件版本字节11";
CM_ SG_ 2483482262 E2P_Cfg4_HW_Ver_Byte12 "ETH硬件版本字节12";
CM_ SG_ 2483482262 E2P_Cfg4_HW_Ver_Byte13 "ETH硬件版本字节13";
CM_ SG_ 2483482262 E2P_Cfg4_HW_Ver_Byte14 "ETH硬件版本字节14";
CM_ SG_ 2483482262 E2P_Cfg4_HW_Ver_Byte15 "ETH硬件版本字节15";
CM_ SG_ 2483482262 E2P_Cfg4_HW_Ver_Byte16 "ETH硬件版本字节16";
CM_ SG_ 2483482263 E2P_Cfg4_HW_Ver_Byte9 "ETH硬件版本字节9";
CM_ SG_ 2483482263 E2P_Cfg4_HW_Ver_Byte10 "ETH硬件版本字节10";
CM_ SG_ 2483482263 E2P_Cfg4_HW_Ver_Byte11 "ETH硬件版本字节11";
CM_ SG_ 2483482263 E2P_Cfg4_HW_Ver_Byte12 "ETH硬件版本字节12";
CM_ SG_ 2483482263 E2P_Cfg4_HW_Ver_Byte13 "ETH硬件版本字节13";
CM_ SG_ 2483482263 E2P_Cfg4_HW_Ver_Byte14 "ETH硬件版本字节14";
CM_ SG_ 2483482263 E2P_Cfg4_HW_Ver_Byte15 "ETH硬件版本字节15";
CM_ SG_ 2483482263 E2P_Cfg4_HW_Ver_Byte16 "ETH硬件版本字节16";
CM_ SG_ 2483482264 E2P_Cfg4_HW_Ver_Byte9 "ETH硬件版本字节9";
CM_ SG_ 2483482264 E2P_Cfg4_HW_Ver_Byte10 "ETH硬件版本字节10";
CM_ SG_ 2483482264 E2P_Cfg4_HW_Ver_Byte11 "ETH硬件版本字节11";
CM_ SG_ 2483482264 E2P_Cfg4_HW_Ver_Byte12 "ETH硬件版本字节12";
CM_ SG_ 2483482264 E2P_Cfg4_HW_Ver_Byte13 "ETH硬件版本字节13";
CM_ SG_ 2483482264 E2P_Cfg4_HW_Ver_Byte14 "ETH硬件版本字节14";
CM_ SG_ 2483482264 E2P_Cfg4_HW_Ver_Byte15 "ETH硬件版本字节15";
CM_ SG_ 2483482264 E2P_Cfg4_HW_Ver_Byte16 "ETH硬件版本字节16";
CM_ SG_ 2483482265 E2P_Cfg4_HW_Ver_Byte9 "ETH硬件版本字节9";
CM_ SG_ 2483482265 E2P_Cfg4_HW_Ver_Byte10 "ETH硬件版本字节10";
CM_ SG_ 2483482265 E2P_Cfg4_HW_Ver_Byte11 "ETH硬件版本字节11";
CM_ SG_ 2483482265 E2P_Cfg4_HW_Ver_Byte12 "ETH硬件版本字节12";
CM_ SG_ 2483482265 E2P_Cfg4_HW_Ver_Byte13 "ETH硬件版本字节13";
CM_ SG_ 2483482265 E2P_Cfg4_HW_Ver_Byte14 "ETH硬件版本字节14";
CM_ SG_ 2483482265 E2P_Cfg4_HW_Ver_Byte15 "ETH硬件版本字节15";
CM_ SG_ 2483482265 E2P_Cfg4_HW_Ver_Byte16 "ETH硬件版本字节16";
CM_ SG_ 2483482266 E2P_Cfg4_HW_Ver_Byte9 "ETH硬件版本字节9";
CM_ SG_ 2483482266 E2P_Cfg4_HW_Ver_Byte10 "ETH硬件版本字节10";
CM_ SG_ 2483482266 E2P_Cfg4_HW_Ver_Byte11 "ETH硬件版本字节11";
CM_ SG_ 2483482266 E2P_Cfg4_HW_Ver_Byte12 "ETH硬件版本字节12";
CM_ SG_ 2483482266 E2P_Cfg4_HW_Ver_Byte13 "ETH硬件版本字节13";
CM_ SG_ 2483482266 E2P_Cfg4_HW_Ver_Byte14 "ETH硬件版本字节14";
CM_ SG_ 2483482266 E2P_Cfg4_HW_Ver_Byte15 "ETH硬件版本字节15";
CM_ SG_ 2483482266 E2P_Cfg4_HW_Ver_Byte16 "ETH硬件版本字节16";
CM_ SG_ 2483482267 E2P_Cfg4_HW_Ver_Byte9 "ETH硬件版本字节9";
CM_ SG_ 2483482267 E2P_Cfg4_HW_Ver_Byte10 "ETH硬件版本字节10";
CM_ SG_ 2483482267 E2P_Cfg4_HW_Ver_Byte11 "ETH硬件版本字节11";
CM_ SG_ 2483482267 E2P_Cfg4_HW_Ver_Byte12 "ETH硬件版本字节12";
CM_ SG_ 2483482267 E2P_Cfg4_HW_Ver_Byte13 "ETH硬件版本字节13";
CM_ SG_ 2483482267 E2P_Cfg4_HW_Ver_Byte14 "ETH硬件版本字节14";
CM_ SG_ 2483482267 E2P_Cfg4_HW_Ver_Byte15 "ETH硬件版本字节15";
CM_ SG_ 2483482267 E2P_Cfg4_HW_Ver_Byte16 "ETH硬件版本字节16";
CM_ SG_ 2483482268 E2P_Cfg4_HW_Ver_Byte9 "ETH硬件版本字节9";
CM_ SG_ 2483482268 E2P_Cfg4_HW_Ver_Byte10 "ETH硬件版本字节10";
CM_ SG_ 2483482268 E2P_Cfg4_HW_Ver_Byte11 "ETH硬件版本字节11";
CM_ SG_ 2483482268 E2P_Cfg4_HW_Ver_Byte12 "ETH硬件版本字节12";
CM_ SG_ 2483482268 E2P_Cfg4_HW_Ver_Byte13 "ETH硬件版本字节13";
CM_ SG_ 2483482268 E2P_Cfg4_HW_Ver_Byte14 "ETH硬件版本字节14";
CM_ SG_ 2483482268 E2P_Cfg4_HW_Ver_Byte15 "ETH硬件版本字节15";
CM_ SG_ 2483482268 E2P_Cfg4_HW_Ver_Byte16 "ETH硬件版本字节16";
CM_ SG_ 2483482269 E2P_Cfg4_HW_Ver_Byte9 "ETH硬件版本字节9";
CM_ SG_ 2483482269 E2P_Cfg4_HW_Ver_Byte10 "ETH硬件版本字节10";
CM_ SG_ 2483482269 E2P_Cfg4_HW_Ver_Byte11 "ETH硬件版本字节11";
CM_ SG_ 2483482269 E2P_Cfg4_HW_Ver_Byte12 "ETH硬件版本字节12";
CM_ SG_ 2483482269 E2P_Cfg4_HW_Ver_Byte13 "ETH硬件版本字节13";
CM_ SG_ 2483482269 E2P_Cfg4_HW_Ver_Byte14 "ETH硬件版本字节14";
CM_ SG_ 2483482269 E2P_Cfg4_HW_Ver_Byte15 "ETH硬件版本字节15";
CM_ SG_ 2483482269 E2P_Cfg4_HW_Ver_Byte16 "ETH硬件版本字节16";
CM_ SG_ 2483482270 E2P_Cfg4_HW_Ver_Byte9 "ETH硬件版本字节9";
CM_ SG_ 2483482270 E2P_Cfg4_HW_Ver_Byte10 "ETH硬件版本字节10";
CM_ SG_ 2483482270 E2P_Cfg4_HW_Ver_Byte11 "ETH硬件版本字节11";
CM_ SG_ 2483482270 E2P_Cfg4_HW_Ver_Byte12 "ETH硬件版本字节12";
CM_ SG_ 2483482270 E2P_Cfg4_HW_Ver_Byte13 "ETH硬件版本字节13";
CM_ SG_ 2483482270 E2P_Cfg4_HW_Ver_Byte14 "ETH硬件版本字节14";
CM_ SG_ 2483482270 E2P_Cfg4_HW_Ver_Byte15 "ETH硬件版本字节15";
CM_ SG_ 2483482270 E2P_Cfg4_HW_Ver_Byte16 "ETH硬件版本字节16";
CM_ SG_ 2483482271 E2P_Cfg4_HW_Ver_Byte9 "ETH硬件版本字节9";
CM_ SG_ 2483482271 E2P_Cfg4_HW_Ver_Byte10 "ETH硬件版本字节10";
CM_ SG_ 2483482271 E2P_Cfg4_HW_Ver_Byte11 "ETH硬件版本字节11";
CM_ SG_ 2483482271 E2P_Cfg4_HW_Ver_Byte12 "ETH硬件版本字节12";
CM_ SG_ 2483482271 E2P_Cfg4_HW_Ver_Byte13 "ETH硬件版本字节13";
CM_ SG_ 2483482271 E2P_Cfg4_HW_Ver_Byte14 "ETH硬件版本字节14";
CM_ SG_ 2483482271 E2P_Cfg4_HW_Ver_Byte15 "ETH硬件版本字节15";
CM_ SG_ 2483482271 E2P_Cfg4_HW_Ver_Byte16 "ETH硬件版本字节16";
CM_ SG_ 2483482272 E2P_Cfg4_HW_Ver_Byte9 "ETH硬件版本字节9";
CM_ SG_ 2483482272 E2P_Cfg4_HW_Ver_Byte10 "ETH硬件版本字节10";
CM_ SG_ 2483482272 E2P_Cfg4_HW_Ver_Byte11 "ETH硬件版本字节11";
CM_ SG_ 2483482272 E2P_Cfg4_HW_Ver_Byte12 "ETH硬件版本字节12";
CM_ SG_ 2483482272 E2P_Cfg4_HW_Ver_Byte13 "ETH硬件版本字节13";
CM_ SG_ 2483482272 E2P_Cfg4_HW_Ver_Byte14 "ETH硬件版本字节14";
CM_ SG_ 2483482272 E2P_Cfg4_HW_Ver_Byte15 "ETH硬件版本字节15";
CM_ SG_ 2483482272 E2P_Cfg4_HW_Ver_Byte16 "ETH硬件版本字节16";
CM_ SG_ 2483482273 E2P_Cfg4_HW_Ver_Byte9 "ETH硬件版本字节9";
CM_ SG_ 2483482273 E2P_Cfg4_HW_Ver_Byte10 "ETH硬件版本字节10";
CM_ SG_ 2483482273 E2P_Cfg4_HW_Ver_Byte11 "ETH硬件版本字节11";
CM_ SG_ 2483482273 E2P_Cfg4_HW_Ver_Byte12 "ETH硬件版本字节12";
CM_ SG_ 2483482273 E2P_Cfg4_HW_Ver_Byte13 "ETH硬件版本字节13";
CM_ SG_ 2483482273 E2P_Cfg4_HW_Ver_Byte14 "ETH硬件版本字节14";
CM_ SG_ 2483482273 E2P_Cfg4_HW_Ver_Byte15 "ETH硬件版本字节15";
CM_ SG_ 2483482273 E2P_Cfg4_HW_Ver_Byte16 "ETH硬件版本字节16";
CM_ SG_ 2483482274 E2P_Cfg4_HW_Ver_Byte9 "ETH硬件版本字节9";
CM_ SG_ 2483482274 E2P_Cfg4_HW_Ver_Byte10 "ETH硬件版本字节10";
CM_ SG_ 2483482274 E2P_Cfg4_HW_Ver_Byte11 "ETH硬件版本字节11";
CM_ SG_ 2483482274 E2P_Cfg4_HW_Ver_Byte12 "ETH硬件版本字节12";
CM_ SG_ 2483482274 E2P_Cfg4_HW_Ver_Byte13 "ETH硬件版本字节13";
CM_ SG_ 2483482274 E2P_Cfg4_HW_Ver_Byte14 "ETH硬件版本字节14";
CM_ SG_ 2483482274 E2P_Cfg4_HW_Ver_Byte15 "ETH硬件版本字节15";
CM_ SG_ 2483482274 E2P_Cfg4_HW_Ver_Byte16 "ETH硬件版本字节16";
CM_ SG_ 2483482275 E2P_Cfg4_HW_Ver_Byte9 "ETH硬件版本字节9";
CM_ SG_ 2483482275 E2P_Cfg4_HW_Ver_Byte10 "ETH硬件版本字节10";
CM_ SG_ 2483482275 E2P_Cfg4_HW_Ver_Byte11 "ETH硬件版本字节11";
CM_ SG_ 2483482275 E2P_Cfg4_HW_Ver_Byte12 "ETH硬件版本字节12";
CM_ SG_ 2483482275 E2P_Cfg4_HW_Ver_Byte13 "ETH硬件版本字节13";
CM_ SG_ 2483482275 E2P_Cfg4_HW_Ver_Byte14 "ETH硬件版本字节14";
CM_ SG_ 2483482275 E2P_Cfg4_HW_Ver_Byte15 "ETH硬件版本字节15";
CM_ SG_ 2483482275 E2P_Cfg4_HW_Ver_Byte16 "ETH硬件版本字节16";
CM_ SG_ 2483482276 E2P_Cfg4_HW_Ver_Byte9 "ETH硬件版本字节9";
CM_ SG_ 2483482276 E2P_Cfg4_HW_Ver_Byte10 "ETH硬件版本字节10";
CM_ SG_ 2483482276 E2P_Cfg4_HW_Ver_Byte11 "ETH硬件版本字节11";
CM_ SG_ 2483482276 E2P_Cfg4_HW_Ver_Byte12 "ETH硬件版本字节12";
CM_ SG_ 2483482276 E2P_Cfg4_HW_Ver_Byte13 "ETH硬件版本字节13";
CM_ SG_ 2483482276 E2P_Cfg4_HW_Ver_Byte14 "ETH硬件版本字节14";
CM_ SG_ 2483482276 E2P_Cfg4_HW_Ver_Byte15 "ETH硬件版本字节15";
CM_ SG_ 2483482276 E2P_Cfg4_HW_Ver_Byte16 "ETH硬件版本字节16";
CM_ SG_ 2483482277 E2P_Cfg4_HW_Ver_Byte9 "ETH硬件版本字节9";
CM_ SG_ 2483482277 E2P_Cfg4_HW_Ver_Byte10 "ETH硬件版本字节10";
CM_ SG_ 2483482277 E2P_Cfg4_HW_Ver_Byte11 "ETH硬件版本字节11";
CM_ SG_ 2483482277 E2P_Cfg4_HW_Ver_Byte12 "ETH硬件版本字节12";
CM_ SG_ 2483482277 E2P_Cfg4_HW_Ver_Byte13 "ETH硬件版本字节13";
CM_ SG_ 2483482277 E2P_Cfg4_HW_Ver_Byte14 "ETH硬件版本字节14";
CM_ SG_ 2483482277 E2P_Cfg4_HW_Ver_Byte15 "ETH硬件版本字节15";
CM_ SG_ 2483482277 E2P_Cfg4_HW_Ver_Byte16 "ETH硬件版本字节16";
CM_ SG_ 2483482278 E2P_Cfg4_HW_Ver_Byte9 "ETH硬件版本字节9";
CM_ SG_ 2483482278 E2P_Cfg4_HW_Ver_Byte10 "ETH硬件版本字节10";
CM_ SG_ 2483482278 E2P_Cfg4_HW_Ver_Byte11 "ETH硬件版本字节11";
CM_ SG_ 2483482278 E2P_Cfg4_HW_Ver_Byte12 "ETH硬件版本字节12";
CM_ SG_ 2483482278 E2P_Cfg4_HW_Ver_Byte13 "ETH硬件版本字节13";
CM_ SG_ 2483482278 E2P_Cfg4_HW_Ver_Byte14 "ETH硬件版本字节14";
CM_ SG_ 2483482278 E2P_Cfg4_HW_Ver_Byte15 "ETH硬件版本字节15";
CM_ SG_ 2483482278 E2P_Cfg4_HW_Ver_Byte16 "ETH硬件版本字节16";
CM_ SG_ 2483482279 E2P_Cfg4_HW_Ver_Byte9 "ETH硬件版本字节9";
CM_ SG_ 2483482279 E2P_Cfg4_HW_Ver_Byte10 "ETH硬件版本字节10";
CM_ SG_ 2483482279 E2P_Cfg4_HW_Ver_Byte11 "ETH硬件版本字节11";
CM_ SG_ 2483482279 E2P_Cfg4_HW_Ver_Byte12 "ETH硬件版本字节12";
CM_ SG_ 2483482279 E2P_Cfg4_HW_Ver_Byte13 "ETH硬件版本字节13";
CM_ SG_ 2483482279 E2P_Cfg4_HW_Ver_Byte14 "ETH硬件版本字节14";
CM_ SG_ 2483482279 E2P_Cfg4_HW_Ver_Byte15 "ETH硬件版本字节15";
CM_ SG_ 2483482279 E2P_Cfg4_HW_Ver_Byte16 "ETH硬件版本字节16";
CM_ SG_ 2483482280 E2P_Cfg4_HW_Ver_Byte9 "ETH硬件版本字节9";
CM_ SG_ 2483482280 E2P_Cfg4_HW_Ver_Byte10 "ETH硬件版本字节10";
CM_ SG_ 2483482280 E2P_Cfg4_HW_Ver_Byte11 "ETH硬件版本字节11";
CM_ SG_ 2483482280 E2P_Cfg4_HW_Ver_Byte12 "ETH硬件版本字节12";
CM_ SG_ 2483482280 E2P_Cfg4_HW_Ver_Byte13 "ETH硬件版本字节13";
CM_ SG_ 2483482280 E2P_Cfg4_HW_Ver_Byte14 "ETH硬件版本字节14";
CM_ SG_ 2483482280 E2P_Cfg4_HW_Ver_Byte15 "ETH硬件版本字节15";
CM_ SG_ 2483482280 E2P_Cfg4_HW_Ver_Byte16 "ETH硬件版本字节16";
CM_ SG_ 2483482281 E2P_Cfg4_HW_Ver_Byte9 "ETH硬件版本字节9";
CM_ SG_ 2483482281 E2P_Cfg4_HW_Ver_Byte10 "ETH硬件版本字节10";
CM_ SG_ 2483482281 E2P_Cfg4_HW_Ver_Byte11 "ETH硬件版本字节11";
CM_ SG_ 2483482281 E2P_Cfg4_HW_Ver_Byte12 "ETH硬件版本字节12";
CM_ SG_ 2483482281 E2P_Cfg4_HW_Ver_Byte13 "ETH硬件版本字节13";
CM_ SG_ 2483482281 E2P_Cfg4_HW_Ver_Byte14 "ETH硬件版本字节14";
CM_ SG_ 2483482281 E2P_Cfg4_HW_Ver_Byte15 "ETH硬件版本字节15";
CM_ SG_ 2483482281 E2P_Cfg4_HW_Ver_Byte16 "ETH硬件版本字节16";
CM_ SG_ 2483482282 E2P_Cfg4_HW_Ver_Byte9 "ETH硬件版本字节9";
CM_ SG_ 2483482282 E2P_Cfg4_HW_Ver_Byte10 "ETH硬件版本字节10";
CM_ SG_ 2483482282 E2P_Cfg4_HW_Ver_Byte11 "ETH硬件版本字节11";
CM_ SG_ 2483482282 E2P_Cfg4_HW_Ver_Byte12 "ETH硬件版本字节12";
CM_ SG_ 2483482282 E2P_Cfg4_HW_Ver_Byte13 "ETH硬件版本字节13";
CM_ SG_ 2483482282 E2P_Cfg4_HW_Ver_Byte14 "ETH硬件版本字节14";
CM_ SG_ 2483482282 E2P_Cfg4_HW_Ver_Byte15 "ETH硬件版本字节15";
CM_ SG_ 2483482282 E2P_Cfg4_HW_Ver_Byte16 "ETH硬件版本字节16";
CM_ SG_ 2483482283 E2P_Cfg4_HW_Ver_Byte9 "ETH硬件版本字节9";
CM_ SG_ 2483482283 E2P_Cfg4_HW_Ver_Byte10 "ETH硬件版本字节10";
CM_ SG_ 2483482283 E2P_Cfg4_HW_Ver_Byte11 "ETH硬件版本字节11";
CM_ SG_ 2483482283 E2P_Cfg4_HW_Ver_Byte12 "ETH硬件版本字节12";
CM_ SG_ 2483482283 E2P_Cfg4_HW_Ver_Byte13 "ETH硬件版本字节13";
CM_ SG_ 2483482283 E2P_Cfg4_HW_Ver_Byte14 "ETH硬件版本字节14";
CM_ SG_ 2483482283 E2P_Cfg4_HW_Ver_Byte15 "ETH硬件版本字节15";
CM_ SG_ 2483482283 E2P_Cfg4_HW_Ver_Byte16 "ETH硬件版本字节16";
CM_ SG_ 2483482284 E2P_Cfg4_HW_Ver_Byte9 "ETH硬件版本字节9";
CM_ SG_ 2483482284 E2P_Cfg4_HW_Ver_Byte10 "ETH硬件版本字节10";
CM_ SG_ 2483482284 E2P_Cfg4_HW_Ver_Byte11 "ETH硬件版本字节11";
CM_ SG_ 2483482284 E2P_Cfg4_HW_Ver_Byte12 "ETH硬件版本字节12";
CM_ SG_ 2483482284 E2P_Cfg4_HW_Ver_Byte13 "ETH硬件版本字节13";
CM_ SG_ 2483482284 E2P_Cfg4_HW_Ver_Byte14 "ETH硬件版本字节14";
CM_ SG_ 2483482284 E2P_Cfg4_HW_Ver_Byte15 "ETH硬件版本字节15";
CM_ SG_ 2483482284 E2P_Cfg4_HW_Ver_Byte16 "ETH硬件版本字节16";
CM_ SG_ 2483482285 E2P_Cfg4_HW_Ver_Byte9 "ETH硬件版本字节9";
CM_ SG_ 2483482285 E2P_Cfg4_HW_Ver_Byte10 "ETH硬件版本字节10";
CM_ SG_ 2483482285 E2P_Cfg4_HW_Ver_Byte11 "ETH硬件版本字节11";
CM_ SG_ 2483482285 E2P_Cfg4_HW_Ver_Byte12 "ETH硬件版本字节12";
CM_ SG_ 2483482285 E2P_Cfg4_HW_Ver_Byte13 "ETH硬件版本字节13";
CM_ SG_ 2483482285 E2P_Cfg4_HW_Ver_Byte14 "ETH硬件版本字节14";
CM_ SG_ 2483482285 E2P_Cfg4_HW_Ver_Byte15 "ETH硬件版本字节15";
CM_ SG_ 2483482285 E2P_Cfg4_HW_Ver_Byte16 "ETH硬件版本字节16";
CM_ SG_ 2483482286 E2P_Cfg4_HW_Ver_Byte9 "ETH硬件版本字节9";
CM_ SG_ 2483482286 E2P_Cfg4_HW_Ver_Byte10 "ETH硬件版本字节10";
CM_ SG_ 2483482286 E2P_Cfg4_HW_Ver_Byte11 "ETH硬件版本字节11";
CM_ SG_ 2483482286 E2P_Cfg4_HW_Ver_Byte12 "ETH硬件版本字节12";
CM_ SG_ 2483482286 E2P_Cfg4_HW_Ver_Byte13 "ETH硬件版本字节13";
CM_ SG_ 2483482286 E2P_Cfg4_HW_Ver_Byte14 "ETH硬件版本字节14";
CM_ SG_ 2483482286 E2P_Cfg4_HW_Ver_Byte15 "ETH硬件版本字节15";
CM_ SG_ 2483482286 E2P_Cfg4_HW_Ver_Byte16 "ETH硬件版本字节16";
CM_ SG_ 2483482287 E2P_Cfg4_HW_Ver_Byte9 "ETH硬件版本字节9";
CM_ SG_ 2483482287 E2P_Cfg4_HW_Ver_Byte10 "ETH硬件版本字节10";
CM_ SG_ 2483482287 E2P_Cfg4_HW_Ver_Byte11 "ETH硬件版本字节11";
CM_ SG_ 2483482287 E2P_Cfg4_HW_Ver_Byte12 "ETH硬件版本字节12";
CM_ SG_ 2483482287 E2P_Cfg4_HW_Ver_Byte13 "ETH硬件版本字节13";
CM_ SG_ 2483482287 E2P_Cfg4_HW_Ver_Byte14 "ETH硬件版本字节14";
CM_ SG_ 2483482287 E2P_Cfg4_HW_Ver_Byte15 "ETH硬件版本字节15";
CM_ SG_ 2483482287 E2P_Cfg4_HW_Ver_Byte16 "ETH硬件版本字节16";
CM_ SG_ 2165465583 L2S_CMD1_CellHeatModeRequ1 "LEMS请求SBMU1进入或退出自加热模式";
CM_ SG_ 2165465583 L2S_CMD1_CellHeatModeRequ2 "LEMS请求SBMU2进入或退出自加热模式";
CM_ SG_ 2165465583 L2S_CMD1_CellHeatModeRequ3 "LEMS请求SBMU3进入或退出自加热模式";
CM_ SG_ 2165465583 L2S_CMD1_Reserve "预留";
CM_ SG_ 2333671233 S2A_BAT_I_HVS_01 "电柜采集电流";
CM_ SG_ 2333671233 BAT_U_HVS_01 "电柜外侧高压采样";
CM_ SG_ 2333671233 BAT_U_TOT_HVS_01 "电柜所有电芯电压累积和";
CM_ SG_ 2333671234 S2A_BAT_I_HVS_02 "电柜采集电流";
CM_ SG_ 2333671234 BAT_U_HVS_02 "电柜外侧高压采样";
CM_ SG_ 2333671234 BAT_U_TOT_HVS_02 "电柜所有电芯电压累积和";
CM_ SG_ 2333671235 S2A_BAT_I_HVS_03 "电柜采集电流";
CM_ SG_ 2333671235 BAT_U_HVS_03 "电柜外侧高压采样";
CM_ SG_ 2333671235 BAT_U_TOT_HVS_03 "电柜所有电芯电压累积和";
CM_ SG_ 2333671236 S2A_BAT_I_HVS_04 "电柜采集电流";
CM_ SG_ 2333671236 BAT_U_HVS_04 "电柜外侧高压采样";
CM_ SG_ 2333671236 BAT_U_TOT_HVS_04 "电柜所有电芯电压累积和";
CM_ SG_ 2333671237 S2A_BAT_I_HVS_05 "电柜采集电流";
CM_ SG_ 2333671237 BAT_U_HVS_05 "电柜外侧高压采样";
CM_ SG_ 2333671237 BAT_U_TOT_HVS_05 "电柜所有电芯电压累积和";
CM_ SG_ 2333671238 S2A_BAT_I_HVS_06 "电柜采集电流";
CM_ SG_ 2333671238 BAT_U_HVS_06 "电柜外侧高压采样";
CM_ SG_ 2333671238 BAT_U_TOT_HVS_06 "电柜所有电芯电压累积和";
CM_ SG_ 2333671239 S2A_BAT_I_HVS_07 "电柜采集电流";
CM_ SG_ 2333671239 BAT_U_HVS_07 "电柜外侧高压采样";
CM_ SG_ 2333671239 BAT_U_TOT_HVS_07 "电柜所有电芯电压累积和";
CM_ SG_ 2333671240 S2A_BAT_I_HVS_08 "电柜采集电流";
CM_ SG_ 2333671240 BAT_U_HVS_08 "电柜外侧高压采样";
CM_ SG_ 2333671240 BAT_U_TOT_HVS_08 "电柜所有电芯电压累积和";
CM_ SG_ 2333671241 S2A_BAT_I_HVS_09 "电柜采集电流";
CM_ SG_ 2333671241 BAT_U_HVS_09 "电柜外侧高压采样";
CM_ SG_ 2333671241 BAT_U_TOT_HVS_09 "电柜所有电芯电压累积和";
CM_ SG_ 2333671242 S2A_BAT_I_HVS_10 "电柜采集电流";
CM_ SG_ 2333671242 BAT_U_HVS_10 "电柜外侧高压采样";
CM_ SG_ 2333671242 BAT_U_TOT_HVS_10 "电柜所有电芯电压累积和";
CM_ SG_ 2333671243 S2A_BAT_I_HVS_11 "电柜采集电流";
CM_ SG_ 2333671243 BAT_U_HVS_11 "电柜外侧高压采样";
CM_ SG_ 2333671243 BAT_U_TOT_HVS_11 "电柜所有电芯电压累积和";
CM_ SG_ 2333671244 S2A_BAT_I_HVS_12 "电柜采集电流";
CM_ SG_ 2333671244 BAT_U_HVS_12 "电柜外侧高压采样";
CM_ SG_ 2333671244 BAT_U_TOT_HVS_12 "电柜所有电芯电压累积和";
CM_ SG_ 2333671245 S2A_BAT_I_HVS_13 "电柜采集电流";
CM_ SG_ 2333671245 BAT_U_HVS_13 "电柜外侧高压采样";
CM_ SG_ 2333671245 BAT_U_TOT_HVS_13 "电柜所有电芯电压累积和";
CM_ SG_ 2333671246 S2A_BAT_I_HVS_14 "电柜采集电流";
CM_ SG_ 2333671246 BAT_U_HVS_14 "电柜外侧高压采样";
CM_ SG_ 2333671246 BAT_U_TOT_HVS_14 "电柜所有电芯电压累积和";
CM_ SG_ 2333671247 S2A_BAT_I_HVS_15 "电柜采集电流";
CM_ SG_ 2333671247 BAT_U_HVS_15 "电柜外侧高压采样";
CM_ SG_ 2333671247 BAT_U_TOT_HVS_15 "电柜所有电芯电压累积和";
CM_ SG_ 2333671248 S2A_BAT_I_HVS_16 "电柜采集电流";
CM_ SG_ 2333671248 BAT_U_HVS_16 "电柜外侧高压采样";
CM_ SG_ 2333671248 BAT_U_TOT_HVS_16 "电柜所有电芯电压累积和";
CM_ SG_ 2333671249 S2A_BAT_I_HVS_17 "电柜采集电流";
CM_ SG_ 2333671249 BAT_U_HVS_17 "电柜外侧高压采样";
CM_ SG_ 2333671249 BAT_U_TOT_HVS_17 "电柜所有电芯电压累积和";
CM_ SG_ 2333671250 S2A_BAT_I_HVS_18 "电柜采集电流";
CM_ SG_ 2333671250 BAT_U_HVS_18 "电柜外侧高压采样";
CM_ SG_ 2333671250 BAT_U_TOT_HVS_18 "电柜所有电芯电压累积和";
CM_ SG_ 2333671251 S2A_BAT_I_HVS_19 "电柜采集电流";
CM_ SG_ 2333671251 BAT_U_HVS_19 "电柜外侧高压采样";
CM_ SG_ 2333671251 BAT_U_TOT_HVS_19 "电柜所有电芯电压累积和";
CM_ SG_ 2333671252 S2A_BAT_I_HVS_20 "电柜采集电流";
CM_ SG_ 2333671252 BAT_U_HVS_20 "电柜外侧高压采样";
CM_ SG_ 2333671252 BAT_U_TOT_HVS_20 "电柜所有电芯电压累积和";
CM_ SG_ 2333671253 S2A_BAT_I_HVS_21 "电柜采集电流";
CM_ SG_ 2333671253 BAT_U_HVS_21 "电柜外侧高压采样";
CM_ SG_ 2333671253 BAT_U_TOT_HVS_21 "电柜所有电芯电压累积和";
CM_ SG_ 2333671254 S2A_BAT_I_HVS_22 "电柜采集电流";
CM_ SG_ 2333671254 BAT_U_HVS_22 "电柜外侧高压采样";
CM_ SG_ 2333671254 BAT_U_TOT_HVS_22 "电柜所有电芯电压累积和";
CM_ SG_ 2333671255 S2A_BAT_I_HVS_23 "电柜采集电流";
CM_ SG_ 2333671255 BAT_U_HVS_23 "电柜外侧高压采样";
CM_ SG_ 2333671255 BAT_U_TOT_HVS_23 "电柜所有电芯电压累积和";
CM_ SG_ 2333671256 S2A_BAT_I_HVS_24 "电柜采集电流";
CM_ SG_ 2333671256 BAT_U_HVS_24 "电柜外侧高压采样";
CM_ SG_ 2333671256 BAT_U_TOT_HVS_24 "电柜所有电芯电压累积和";
CM_ SG_ 2333671257 S2A_BAT_I_HVS_25 "电柜采集电流";
CM_ SG_ 2333671257 BAT_U_HVS_25 "电柜外侧高压采样";
CM_ SG_ 2333671257 BAT_U_TOT_HVS_25 "电柜所有电芯电压累积和";
CM_ SG_ 2333671258 S2A_BAT_I_HVS_26 "电柜采集电流";
CM_ SG_ 2333671258 BAT_U_HVS_26 "电柜外侧高压采样";
CM_ SG_ 2333671258 BAT_U_TOT_HVS_26 "电柜所有电芯电压累积和";
CM_ SG_ 2333671259 S2A_BAT_I_HVS_27 "电柜采集电流";
CM_ SG_ 2333671259 BAT_U_HVS_27 "电柜外侧高压采样";
CM_ SG_ 2333671259 BAT_U_TOT_HVS_27 "电柜所有电芯电压累积和";
CM_ SG_ 2333671260 S2A_BAT_I_HVS_28 "电柜采集电流";
CM_ SG_ 2333671260 BAT_U_HVS_28 "电柜外侧高压采样";
CM_ SG_ 2333671260 BAT_U_TOT_HVS_28 "电柜所有电芯电压累积和";
CM_ SG_ 2333671261 S2A_BAT_I_HVS_29 "电柜采集电流";
CM_ SG_ 2333671261 BAT_U_HVS_29 "电柜外侧高压采样";
CM_ SG_ 2333671261 BAT_U_TOT_HVS_29 "电柜所有电芯电压累积和";
CM_ SG_ 2333671262 S2A_BAT_I_HVS_30 "电柜采集电流";
CM_ SG_ 2333671262 BAT_U_HVS_30 "电柜外侧高压采样";
CM_ SG_ 2333671262 BAT_U_TOT_HVS_30 "电柜所有电芯电压累积和";
CM_ SG_ 2333671263 S2A_BAT_I_HVS_31 "电柜采集电流";
CM_ SG_ 2333671263 BAT_U_HVS_31 "电柜外侧高压采样";
CM_ SG_ 2333671263 BAT_U_TOT_HVS_31 "电柜所有电芯电压累积和";
CM_ SG_ 2333671264 S2A_BAT_I_HVS_32 "电柜采集电流";
CM_ SG_ 2333671264 BAT_U_HVS_32 "电柜外侧高压采样";
CM_ SG_ 2333671264 BAT_U_TOT_HVS_32 "电柜所有电芯电压累积和";
CM_ SG_ 2333671265 S2A_BAT_I_HVS_33 "电柜采集电流";
CM_ SG_ 2333671265 BAT_U_HVS_33 "电柜外侧高压采样";
CM_ SG_ 2333671265 BAT_U_TOT_HVS_33 "电柜所有电芯电压累积和";
CM_ SG_ 2333671266 S2A_BAT_I_HVS_34 "电柜采集电流";
CM_ SG_ 2333671266 BAT_U_HVS_34 "电柜外侧高压采样";
CM_ SG_ 2333671266 BAT_U_TOT_HVS_34 "电柜所有电芯电压累积和";
CM_ SG_ 2333671267 S2A_BAT_I_HVS_35 "电柜采集电流";
CM_ SG_ 2333671267 BAT_U_HVS_35 "电柜外侧高压采样";
CM_ SG_ 2333671267 BAT_U_TOT_HVS_35 "电柜所有电芯电压累积和";
CM_ SG_ 2333671268 S2A_BAT_I_HVS_36 "电柜采集电流";
CM_ SG_ 2333671268 BAT_U_HVS_36 "电柜外侧高压采样";
CM_ SG_ 2333671268 BAT_U_TOT_HVS_36 "电柜所有电芯电压累积和";
CM_ SG_ 2333671269 S2A_BAT_I_HVS_37 "电柜采集电流";
CM_ SG_ 2333671269 BAT_U_HVS_37 "电柜外侧高压采样";
CM_ SG_ 2333671269 BAT_U_TOT_HVS_37 "电柜所有电芯电压累积和";
CM_ SG_ 2333671270 S2A_BAT_I_HVS_38 "电柜采集电流";
CM_ SG_ 2333671270 BAT_U_HVS_38 "电柜外侧高压采样";
CM_ SG_ 2333671270 BAT_U_TOT_HVS_38 "电柜所有电芯电压累积和";
CM_ SG_ 2333671271 S2A_BAT_I_HVS_39 "电柜采集电流";
CM_ SG_ 2333671271 BAT_U_HVS_39 "电柜外侧高压采样";
CM_ SG_ 2333671271 BAT_U_TOT_HVS_39 "电柜所有电芯电压累积和";
CM_ SG_ 2333671272 S2A_BAT_I_HVS_40 "电柜采集电流";
CM_ SG_ 2333671272 BAT_U_HVS_40 "电柜外侧高压采样";
CM_ SG_ 2333671272 BAT_U_TOT_HVS_40 "电柜所有电芯电压累积和";
CM_ SG_ 2333671273 S2A_BAT_I_HVS_41 "电柜采集电流";
CM_ SG_ 2333671273 BAT_U_HVS_41 "电柜外侧高压采样";
CM_ SG_ 2333671273 BAT_U_TOT_HVS_41 "电柜所有电芯电压累积和";
CM_ SG_ 2333671274 S2A_BAT_I_HVS_42 "电柜采集电流";
CM_ SG_ 2333671274 BAT_U_HVS_42 "电柜外侧高压采样";
CM_ SG_ 2333671274 BAT_U_TOT_HVS_42 "电柜所有电芯电压累积和";
CM_ SG_ 2333671275 S2A_BAT_I_HVS_43 "电柜采集电流";
CM_ SG_ 2333671275 BAT_U_HVS_43 "电柜外侧高压采样";
CM_ SG_ 2333671275 BAT_U_TOT_HVS_43 "电柜所有电芯电压累积和";
CM_ SG_ 2333671276 S2A_BAT_I_HVS_44 "电柜采集电流";
CM_ SG_ 2333671276 BAT_U_HVS_44 "电柜外侧高压采样";
CM_ SG_ 2333671276 BAT_U_TOT_HVS_44 "电柜所有电芯电压累积和";
CM_ SG_ 2333671277 S2A_BAT_I_HVS_45 "电柜采集电流";
CM_ SG_ 2333671277 BAT_U_HVS_45 "电柜外侧高压采样";
CM_ SG_ 2333671277 BAT_U_TOT_HVS_45 "电柜所有电芯电压累积和";
CM_ SG_ 2333671278 S2A_BAT_I_HVS_46 "电柜采集电流";
CM_ SG_ 2333671278 BAT_U_HVS_46 "电柜外侧高压采样";
CM_ SG_ 2333671278 BAT_U_TOT_HVS_46 "电柜所有电芯电压累积和";
CM_ SG_ 2333671279 S2A_BAT_I_HVS_47 "电柜采集电流";
CM_ SG_ 2333671279 BAT_U_HVS_47 "电柜外侧高压采样";
CM_ SG_ 2333671279 BAT_U_TOT_HVS_47 "电柜所有电芯电压累积和";
CM_ SG_ 2333671280 S2A_BAT_I_HVS_48 "电柜采集电流";
CM_ SG_ 2333671280 BAT_U_HVS_48 "电柜外侧高压采样";
CM_ SG_ 2333671280 BAT_U_TOT_HVS_48 "电柜所有电芯电压累积和";
CM_ SG_ 2333671281 S2A_BAT_I_HVS_49 "电柜采集电流";
CM_ SG_ 2333671281 BAT_U_HVS_49 "电柜外侧高压采样";
CM_ SG_ 2333671281 BAT_U_TOT_HVS_49 "电柜所有电芯电压累积和";
CM_ SG_ 2333671282 S2A_BAT_I_HVS_50 "电柜采集电流";
CM_ SG_ 2333671282 BAT_U_HVS_50 "电柜外侧高压采样";
CM_ SG_ 2333671282 BAT_U_TOT_HVS_50 "电柜所有电芯电压累积和";
CM_ SG_ 2333671283 S2A_BAT_I_HVS_51 "电柜采集电流";
CM_ SG_ 2333671283 BAT_U_HVS_51 "电柜外侧高压采样";
CM_ SG_ 2333671283 BAT_U_TOT_HVS_51 "电柜所有电芯电压累积和";
CM_ SG_ 2333671284 S2A_BAT_I_HVS_52 "电柜采集电流";
CM_ SG_ 2333671284 BAT_U_HVS_52 "电柜外侧高压采样";
CM_ SG_ 2333671284 BAT_U_TOT_HVS_52 "电柜所有电芯电压累积和";
CM_ SG_ 2333671285 S2A_BAT_I_HVS_53 "电柜采集电流";
CM_ SG_ 2333671285 BAT_U_HVS_53 "电柜外侧高压采样";
CM_ SG_ 2333671285 BAT_U_TOT_HVS_53 "电柜所有电芯电压累积和";
CM_ SG_ 2333671286 S2A_BAT_I_HVS_54 "电柜采集电流";
CM_ SG_ 2333671286 BAT_U_HVS_54 "电柜外侧高压采样";
CM_ SG_ 2333671286 BAT_U_TOT_HVS_54 "电柜所有电芯电压累积和";
CM_ SG_ 2333671287 S2A_BAT_I_HVS_55 "电柜采集电流";
CM_ SG_ 2333671287 BAT_U_HVS_55 "电柜外侧高压采样";
CM_ SG_ 2333671287 BAT_U_TOT_HVS_55 "电柜所有电芯电压累积和";
CM_ SG_ 2333671288 S2A_BAT_I_HVS_56 "电柜采集电流";
CM_ SG_ 2333671288 BAT_U_HVS_56 "电柜外侧高压采样";
CM_ SG_ 2333671288 BAT_U_TOT_HVS_56 "电柜所有电芯电压累积和";
CM_ SG_ 2333671289 S2A_BAT_I_HVS_57 "电柜采集电流";
CM_ SG_ 2333671289 BAT_U_HVS_57 "电柜外侧高压采样";
CM_ SG_ 2333671289 BAT_U_TOT_HVS_57 "电柜所有电芯电压累积和";
CM_ SG_ 2333671290 S2A_BAT_I_HVS_58 "电柜采集电流";
CM_ SG_ 2333671290 BAT_U_HVS_58 "电柜外侧高压采样";
CM_ SG_ 2333671290 BAT_U_TOT_HVS_58 "电柜所有电芯电压累积和";
CM_ SG_ 2333671291 S2A_BAT_I_HVS_59 "电柜采集电流";
CM_ SG_ 2333671291 BAT_U_HVS_59 "电柜外侧高压采样";
CM_ SG_ 2333671291 BAT_U_TOT_HVS_59 "电柜所有电芯电压累积和";
CM_ SG_ 2333671292 S2A_BAT_I_HVS_60 "电柜采集电流";
CM_ SG_ 2333671292 BAT_U_HVS_60 "电柜外侧高压采样";
CM_ SG_ 2333671292 BAT_U_TOT_HVS_60 "电柜所有电芯电压累积和";
CM_ SG_ 2333671293 S2A_BAT_I_HVS_61 "电柜采集电流";
CM_ SG_ 2333671293 BAT_U_HVS_61 "电柜外侧高压采样";
CM_ SG_ 2333671293 BAT_U_TOT_HVS_61 "电柜所有电芯电压累积和";
CM_ SG_ 2333671294 S2A_BAT_I_HVS_62 "电柜采集电流";
CM_ SG_ 2333671294 BAT_U_HVS_62 "电柜外侧高压采样";
CM_ SG_ 2333671294 BAT_U_TOT_HVS_62 "电柜所有电芯电压累积和";
CM_ SG_ 2333671295 S2A_BAT_I_HVS_63 "电柜采集电流";
CM_ SG_ 2333671295 BAT_U_HVS_63 "电柜外侧高压采样";
CM_ SG_ 2333671295 BAT_U_TOT_HVS_63 "电柜所有电芯电压累积和";
CM_ SG_ 2400644673 CSC_Tpole_No_01 "CSC号";
CM_ SG_ 2400644673 CSC_Tpole_Frame_Index_01 "当前CSC中温度数据帧序号";
CM_ SG_ 2400644673 CSC_Tpole_01_01 "电极温度01";
CM_ SG_ 2400644673 CSC_Tpole_02_01 "电极温度02";
CM_ SG_ 2400644673 CSC_Tpole_03_01 "电极温度03";
CM_ SG_ 2400644673 CSC_Tpole_04_01 "电极温度04";
CM_ SG_ 2400644673 CSC_Tpole_05_01 "电极温度05";
CM_ SG_ 2400644673 CSC_Tpole_06_01 "电极温度06";
CM_ SG_ 2400644674 CSC_Tpole_No_02 "CSC号";
CM_ SG_ 2400644674 CSC_Tpole_Frame_Index_02 "当前CSC中温度数据帧序号";
CM_ SG_ 2400644674 CSC_Tpole_01_02 "电极温度01";
CM_ SG_ 2400644674 CSC_Tpole_02_02 "电极温度02";
CM_ SG_ 2400644674 CSC_Tpole_03_02 "电极温度03";
CM_ SG_ 2400644674 CSC_Tpole_04_02 "电极温度04";
CM_ SG_ 2400644674 CSC_Tpole_05_02 "电极温度05";
CM_ SG_ 2400644674 CSC_Tpole_06_02 "电极温度06";
CM_ SG_ 2400644675 CSC_Tpole_No_03 "CSC号";
CM_ SG_ 2400644675 CSC_Tpole_Frame_Index_03 "当前CSC中温度数据帧序号";
CM_ SG_ 2400644675 CSC_Tpole_01_03 "电极温度01";
CM_ SG_ 2400644675 CSC_Tpole_02_03 "电极温度02";
CM_ SG_ 2400644675 CSC_Tpole_03_03 "电极温度03";
CM_ SG_ 2400644675 CSC_Tpole_04_03 "电极温度04";
CM_ SG_ 2400644675 CSC_Tpole_05_03 "电极温度05";
CM_ SG_ 2400644675 CSC_Tpole_06_03 "电极温度06";
CM_ SG_ 2400644676 CSC_Tpole_No_04 "CSC号";
CM_ SG_ 2400644676 CSC_Tpole_Frame_Index_04 "当前CSC中温度数据帧序号";
CM_ SG_ 2400644676 CSC_Tpole_01_04 "电极温度01";
CM_ SG_ 2400644676 CSC_Tpole_02_04 "电极温度02";
CM_ SG_ 2400644676 CSC_Tpole_03_04 "电极温度03";
CM_ SG_ 2400644676 CSC_Tpole_04_04 "电极温度04";
CM_ SG_ 2400644676 CSC_Tpole_05_04 "电极温度05";
CM_ SG_ 2400644676 CSC_Tpole_06_04 "电极温度06";
CM_ SG_ 2400644677 CSC_Tpole_No_05 "CSC号";
CM_ SG_ 2400644677 CSC_Tpole_Frame_Index_05 "当前CSC中温度数据帧序号";
CM_ SG_ 2400644677 CSC_Tpole_01_05 "电极温度01";
CM_ SG_ 2400644677 CSC_Tpole_02_05 "电极温度02";
CM_ SG_ 2400644677 CSC_Tpole_03_05 "电极温度03";
CM_ SG_ 2400644677 CSC_Tpole_04_05 "电极温度04";
CM_ SG_ 2400644677 CSC_Tpole_05_05 "电极温度05";
CM_ SG_ 2400644677 CSC_Tpole_06_05 "电极温度06";
CM_ SG_ 2400644678 CSC_Tpole_No_06 "CSC号";
CM_ SG_ 2400644678 CSC_Tpole_Frame_Index_06 "当前CSC中温度数据帧序号";
CM_ SG_ 2400644678 CSC_Tpole_01_06 "电极温度01";
CM_ SG_ 2400644678 CSC_Tpole_02_06 "电极温度02";
CM_ SG_ 2400644678 CSC_Tpole_03_06 "电极温度03";
CM_ SG_ 2400644678 CSC_Tpole_04_06 "电极温度04";
CM_ SG_ 2400644678 CSC_Tpole_05_06 "电极温度05";
CM_ SG_ 2400644678 CSC_Tpole_06_06 "电极温度06";
CM_ SG_ 2400644679 CSC_Tpole_No_07 "CSC号";
CM_ SG_ 2400644679 CSC_Tpole_Frame_Index_07 "当前CSC中温度数据帧序号";
CM_ SG_ 2400644679 CSC_Tpole_01_07 "电极温度01";
CM_ SG_ 2400644679 CSC_Tpole_02_07 "电极温度02";
CM_ SG_ 2400644679 CSC_Tpole_03_07 "电极温度03";
CM_ SG_ 2400644679 CSC_Tpole_04_07 "电极温度04";
CM_ SG_ 2400644679 CSC_Tpole_05_07 "电极温度05";
CM_ SG_ 2400644679 CSC_Tpole_06_07 "电极温度06";
CM_ SG_ 2400644680 CSC_Tpole_No_08 "CSC号";
CM_ SG_ 2400644680 CSC_Tpole_Frame_Index_08 "当前CSC中温度数据帧序号";
CM_ SG_ 2400644680 CSC_Tpole_01_08 "电极温度01";
CM_ SG_ 2400644680 CSC_Tpole_02_08 "电极温度02";
CM_ SG_ 2400644680 CSC_Tpole_03_08 "电极温度03";
CM_ SG_ 2400644680 CSC_Tpole_04_08 "电极温度04";
CM_ SG_ 2400644680 CSC_Tpole_05_08 "电极温度05";
CM_ SG_ 2400644680 CSC_Tpole_06_08 "电极温度06";
CM_ SG_ 2400644681 CSC_Tpole_No_09 "CSC号";
CM_ SG_ 2400644681 CSC_Tpole_Frame_Index_09 "当前CSC中温度数据帧序号";
CM_ SG_ 2400644681 CSC_Tpole_01_09 "电极温度01";
CM_ SG_ 2400644681 CSC_Tpole_02_09 "电极温度02";
CM_ SG_ 2400644681 CSC_Tpole_03_09 "电极温度03";
CM_ SG_ 2400644681 CSC_Tpole_04_09 "电极温度04";
CM_ SG_ 2400644681 CSC_Tpole_05_09 "电极温度05";
CM_ SG_ 2400644681 CSC_Tpole_06_09 "电极温度06";
CM_ SG_ 2400644682 CSC_Tpole_No_10 "CSC号";
CM_ SG_ 2400644682 CSC_Tpole_Frame_Index_10 "当前CSC中温度数据帧序号";
CM_ SG_ 2400644682 CSC_Tpole_01_10 "电极温度01";
CM_ SG_ 2400644682 CSC_Tpole_02_10 "电极温度02";
CM_ SG_ 2400644682 CSC_Tpole_03_10 "电极温度03";
CM_ SG_ 2400644682 CSC_Tpole_04_10 "电极温度04";
CM_ SG_ 2400644682 CSC_Tpole_05_10 "电极温度05";
CM_ SG_ 2400644682 CSC_Tpole_06_10 "电极温度06";
CM_ SG_ 2400644683 CSC_Tpole_No_11 "CSC号";
CM_ SG_ 2400644683 CSC_Tpole_Frame_Index_11 "当前CSC中温度数据帧序号";
CM_ SG_ 2400644683 CSC_Tpole_01_11 "电极温度01";
CM_ SG_ 2400644683 CSC_Tpole_02_11 "电极温度02";
CM_ SG_ 2400644683 CSC_Tpole_03_11 "电极温度03";
CM_ SG_ 2400644683 CSC_Tpole_04_11 "电极温度04";
CM_ SG_ 2400644683 CSC_Tpole_05_11 "电极温度05";
CM_ SG_ 2400644683 CSC_Tpole_06_11 "电极温度06";
CM_ SG_ 2400644684 CSC_Tpole_No_12 "CSC号";
CM_ SG_ 2400644684 CSC_Tpole_Frame_Index_12 "当前CSC中温度数据帧序号";
CM_ SG_ 2400644684 CSC_Tpole_01_12 "电极温度01";
CM_ SG_ 2400644684 CSC_Tpole_02_12 "电极温度02";
CM_ SG_ 2400644684 CSC_Tpole_03_12 "电极温度03";
CM_ SG_ 2400644684 CSC_Tpole_04_12 "电极温度04";
CM_ SG_ 2400644684 CSC_Tpole_05_12 "电极温度05";
CM_ SG_ 2400644684 CSC_Tpole_06_12 "电极温度06";
CM_ SG_ 2400644685 CSC_Tpole_No_13 "CSC号";
CM_ SG_ 2400644685 CSC_Tpole_Frame_Index_13 "当前CSC中温度数据帧序号";
CM_ SG_ 2400644685 CSC_Tpole_01_13 "电极温度01";
CM_ SG_ 2400644685 CSC_Tpole_02_13 "电极温度02";
CM_ SG_ 2400644685 CSC_Tpole_03_13 "电极温度03";
CM_ SG_ 2400644685 CSC_Tpole_04_13 "电极温度04";
CM_ SG_ 2400644685 CSC_Tpole_05_13 "电极温度05";
CM_ SG_ 2400644685 CSC_Tpole_06_13 "电极温度06";
CM_ SG_ 2400644686 CSC_Tpole_No_14 "CSC号";
CM_ SG_ 2400644686 CSC_Tpole_Frame_Index_14 "当前CSC中温度数据帧序号";
CM_ SG_ 2400644686 CSC_Tpole_01_14 "电极温度01";
CM_ SG_ 2400644686 CSC_Tpole_02_14 "电极温度02";
CM_ SG_ 2400644686 CSC_Tpole_03_14 "电极温度03";
CM_ SG_ 2400644686 CSC_Tpole_04_14 "电极温度04";
CM_ SG_ 2400644686 CSC_Tpole_05_14 "电极温度05";
CM_ SG_ 2400644686 CSC_Tpole_06_14 "电极温度06";
CM_ SG_ 2400644687 CSC_Tpole_No_15 "CSC号";
CM_ SG_ 2400644687 CSC_Tpole_Frame_Index_15 "当前CSC中温度数据帧序号";
CM_ SG_ 2400644687 CSC_Tpole_01_15 "电极温度01";
CM_ SG_ 2400644687 CSC_Tpole_02_15 "电极温度02";
CM_ SG_ 2400644687 CSC_Tpole_03_15 "电极温度03";
CM_ SG_ 2400644687 CSC_Tpole_04_15 "电极温度04";
CM_ SG_ 2400644687 CSC_Tpole_05_15 "电极温度05";
CM_ SG_ 2400644687 CSC_Tpole_06_15 "电极温度06";
CM_ SG_ 2400644688 CSC_Tpole_No_16 "CSC号";
CM_ SG_ 2400644688 CSC_Tpole_Frame_Index_16 "当前CSC中温度数据帧序号";
CM_ SG_ 2400644688 CSC_Tpole_01_16 "电极温度01";
CM_ SG_ 2400644688 CSC_Tpole_02_16 "电极温度02";
CM_ SG_ 2400644688 CSC_Tpole_03_16 "电极温度03";
CM_ SG_ 2400644688 CSC_Tpole_04_16 "电极温度04";
CM_ SG_ 2400644688 CSC_Tpole_05_16 "电极温度05";
CM_ SG_ 2400644688 CSC_Tpole_06_16 "电极温度06";
CM_ SG_ 2400644689 CSC_Tpole_No_17 "CSC号";
CM_ SG_ 2400644689 CSC_Tpole_Frame_Index_17 "当前CSC中温度数据帧序号";
CM_ SG_ 2400644689 CSC_Tpole_01_17 "电极温度01";
CM_ SG_ 2400644689 CSC_Tpole_02_17 "电极温度02";
CM_ SG_ 2400644689 CSC_Tpole_03_17 "电极温度03";
CM_ SG_ 2400644689 CSC_Tpole_04_17 "电极温度04";
CM_ SG_ 2400644689 CSC_Tpole_05_17 "电极温度05";
CM_ SG_ 2400644689 CSC_Tpole_06_17 "电极温度06";
CM_ SG_ 2400644690 CSC_Tpole_No_18 "CSC号";
CM_ SG_ 2400644690 CSC_Tpole_Frame_Index_18 "当前CSC中温度数据帧序号";
CM_ SG_ 2400644690 CSC_Tpole_01_18 "电极温度01";
CM_ SG_ 2400644690 CSC_Tpole_02_18 "电极温度02";
CM_ SG_ 2400644690 CSC_Tpole_03_18 "电极温度03";
CM_ SG_ 2400644690 CSC_Tpole_04_18 "电极温度04";
CM_ SG_ 2400644690 CSC_Tpole_05_18 "电极温度05";
CM_ SG_ 2400644690 CSC_Tpole_06_18 "电极温度06";
CM_ SG_ 2400644691 CSC_Tpole_No_19 "CSC号";
CM_ SG_ 2400644691 CSC_Tpole_Frame_Index_19 "当前CSC中温度数据帧序号";
CM_ SG_ 2400644691 CSC_Tpole_01_19 "电极温度01";
CM_ SG_ 2400644691 CSC_Tpole_02_19 "电极温度02";
CM_ SG_ 2400644691 CSC_Tpole_03_19 "电极温度03";
CM_ SG_ 2400644691 CSC_Tpole_04_19 "电极温度04";
CM_ SG_ 2400644691 CSC_Tpole_05_19 "电极温度05";
CM_ SG_ 2400644691 CSC_Tpole_06_19 "电极温度06";
CM_ SG_ 2400644692 CSC_Tpole_No_20 "CSC号";
CM_ SG_ 2400644692 CSC_Tpole_Frame_Index_20 "当前CSC中温度数据帧序号";
CM_ SG_ 2400644692 CSC_Tpole_01_20 "电极温度01";
CM_ SG_ 2400644692 CSC_Tpole_02_20 "电极温度02";
CM_ SG_ 2400644692 CSC_Tpole_03_20 "电极温度03";
CM_ SG_ 2400644692 CSC_Tpole_04_20 "电极温度04";
CM_ SG_ 2400644692 CSC_Tpole_05_20 "电极温度05";
CM_ SG_ 2400644692 CSC_Tpole_06_20 "电极温度06";
CM_ SG_ 2400644693 CSC_Tpole_No_21 "CSC号";
CM_ SG_ 2400644693 CSC_Tpole_Frame_Index_21 "当前CSC中温度数据帧序号";
CM_ SG_ 2400644693 CSC_Tpole_01_21 "电极温度01";
CM_ SG_ 2400644693 CSC_Tpole_02_21 "电极温度02";
CM_ SG_ 2400644693 CSC_Tpole_03_21 "电极温度03";
CM_ SG_ 2400644693 CSC_Tpole_04_21 "电极温度04";
CM_ SG_ 2400644693 CSC_Tpole_05_21 "电极温度05";
CM_ SG_ 2400644693 CSC_Tpole_06_21 "电极温度06";
CM_ SG_ 2400644694 CSC_Tpole_No_22 "CSC号";
CM_ SG_ 2400644694 CSC_Tpole_Frame_Index_22 "当前CSC中温度数据帧序号";
CM_ SG_ 2400644694 CSC_Tpole_01_22 "电极温度01";
CM_ SG_ 2400644694 CSC_Tpole_02_22 "电极温度02";
CM_ SG_ 2400644694 CSC_Tpole_03_22 "电极温度03";
CM_ SG_ 2400644694 CSC_Tpole_04_22 "电极温度04";
CM_ SG_ 2400644694 CSC_Tpole_05_22 "电极温度05";
CM_ SG_ 2400644694 CSC_Tpole_06_22 "电极温度06";
CM_ SG_ 2400644695 CSC_Tpole_No_23 "CSC号";
CM_ SG_ 2400644695 CSC_Tpole_Frame_Index_23 "当前CSC中温度数据帧序号";
CM_ SG_ 2400644695 CSC_Tpole_01_23 "电极温度01";
CM_ SG_ 2400644695 CSC_Tpole_02_23 "电极温度02";
CM_ SG_ 2400644695 CSC_Tpole_03_23 "电极温度03";
CM_ SG_ 2400644695 CSC_Tpole_04_23 "电极温度04";
CM_ SG_ 2400644695 CSC_Tpole_05_23 "电极温度05";
CM_ SG_ 2400644695 CSC_Tpole_06_23 "电极温度06";
CM_ SG_ 2400644696 CSC_Tpole_No_24 "CSC号";
CM_ SG_ 2400644696 CSC_Tpole_Frame_Index_24 "当前CSC中温度数据帧序号";
CM_ SG_ 2400644696 CSC_Tpole_01_24 "电极温度01";
CM_ SG_ 2400644696 CSC_Tpole_02_24 "电极温度02";
CM_ SG_ 2400644696 CSC_Tpole_03_24 "电极温度03";
CM_ SG_ 2400644696 CSC_Tpole_04_24 "电极温度04";
CM_ SG_ 2400644696 CSC_Tpole_05_24 "电极温度05";
CM_ SG_ 2400644696 CSC_Tpole_06_24 "电极温度06";
CM_ SG_ 2400644697 CSC_Tpole_No_25 "CSC号";
CM_ SG_ 2400644697 CSC_Tpole_Frame_Index_25 "当前CSC中温度数据帧序号";
CM_ SG_ 2400644697 CSC_Tpole_01_25 "电极温度01";
CM_ SG_ 2400644697 CSC_Tpole_02_25 "电极温度02";
CM_ SG_ 2400644697 CSC_Tpole_03_25 "电极温度03";
CM_ SG_ 2400644697 CSC_Tpole_04_25 "电极温度04";
CM_ SG_ 2400644697 CSC_Tpole_05_25 "电极温度05";
CM_ SG_ 2400644697 CSC_Tpole_06_25 "电极温度06";
CM_ SG_ 2400644698 CSC_Tpole_No_26 "CSC号";
CM_ SG_ 2400644698 CSC_Tpole_Frame_Index_26 "当前CSC中温度数据帧序号";
CM_ SG_ 2400644698 CSC_Tpole_01_26 "电极温度01";
CM_ SG_ 2400644698 CSC_Tpole_02_26 "电极温度02";
CM_ SG_ 2400644698 CSC_Tpole_03_26 "电极温度03";
CM_ SG_ 2400644698 CSC_Tpole_04_26 "电极温度04";
CM_ SG_ 2400644698 CSC_Tpole_05_26 "电极温度05";
CM_ SG_ 2400644698 CSC_Tpole_06_26 "电极温度06";
CM_ SG_ 2400644699 CSC_Tpole_No_27 "CSC号";
CM_ SG_ 2400644699 CSC_Tpole_Frame_Index_27 "当前CSC中温度数据帧序号";
CM_ SG_ 2400644699 CSC_Tpole_01_27 "电极温度01";
CM_ SG_ 2400644699 CSC_Tpole_02_27 "电极温度02";
CM_ SG_ 2400644699 CSC_Tpole_03_27 "电极温度03";
CM_ SG_ 2400644699 CSC_Tpole_04_27 "电极温度04";
CM_ SG_ 2400644699 CSC_Tpole_05_27 "电极温度05";
CM_ SG_ 2400644699 CSC_Tpole_06_27 "电极温度06";
CM_ SG_ 2400644700 CSC_Tpole_No_28 "CSC号";
CM_ SG_ 2400644700 CSC_Tpole_Frame_Index_28 "当前CSC中温度数据帧序号";
CM_ SG_ 2400644700 CSC_Tpole_01_28 "电极温度01";
CM_ SG_ 2400644700 CSC_Tpole_02_28 "电极温度02";
CM_ SG_ 2400644700 CSC_Tpole_03_28 "电极温度03";
CM_ SG_ 2400644700 CSC_Tpole_04_28 "电极温度04";
CM_ SG_ 2400644700 CSC_Tpole_05_28 "电极温度05";
CM_ SG_ 2400644700 CSC_Tpole_06_28 "电极温度06";
CM_ SG_ 2400644701 CSC_Tpole_No_29 "CSC号";
CM_ SG_ 2400644701 CSC_Tpole_Frame_Index_29 "当前CSC中温度数据帧序号";
CM_ SG_ 2400644701 CSC_Tpole_01_29 "电极温度01";
CM_ SG_ 2400644701 CSC_Tpole_02_29 "电极温度02";
CM_ SG_ 2400644701 CSC_Tpole_03_29 "电极温度03";
CM_ SG_ 2400644701 CSC_Tpole_04_29 "电极温度04";
CM_ SG_ 2400644701 CSC_Tpole_05_29 "电极温度05";
CM_ SG_ 2400644701 CSC_Tpole_06_29 "电极温度06";
CM_ SG_ 2400644702 CSC_Tpole_No_30 "CSC号";
CM_ SG_ 2400644702 CSC_Tpole_Frame_Index_30 "当前CSC中温度数据帧序号";
CM_ SG_ 2400644702 CSC_Tpole_01_30 "电极温度01";
CM_ SG_ 2400644702 CSC_Tpole_02_30 "电极温度02";
CM_ SG_ 2400644702 CSC_Tpole_03_30 "电极温度03";
CM_ SG_ 2400644702 CSC_Tpole_04_30 "电极温度04";
CM_ SG_ 2400644702 CSC_Tpole_05_30 "电极温度05";
CM_ SG_ 2400644702 CSC_Tpole_06_30 "电极温度06";
CM_ SG_ 2400644703 CSC_Tpole_No_31 "CSC号";
CM_ SG_ 2400644703 CSC_Tpole_Frame_Index_31 "当前CSC中温度数据帧序号";
CM_ SG_ 2400644703 CSC_Tpole_01_31 "电极温度01";
CM_ SG_ 2400644703 CSC_Tpole_02_31 "电极温度02";
CM_ SG_ 2400644703 CSC_Tpole_03_31 "电极温度03";
CM_ SG_ 2400644703 CSC_Tpole_04_31 "电极温度04";
CM_ SG_ 2400644703 CSC_Tpole_05_31 "电极温度05";
CM_ SG_ 2400644703 CSC_Tpole_06_31 "电极温度06";
CM_ SG_ 2400644704 CSC_Tpole_No_32 "CSC号";
CM_ SG_ 2400644704 CSC_Tpole_Frame_Index_32 "当前CSC中温度数据帧序号";
CM_ SG_ 2400644704 CSC_Tpole_01_32 "电极温度01";
CM_ SG_ 2400644704 CSC_Tpole_02_32 "电极温度02";
CM_ SG_ 2400644704 CSC_Tpole_03_32 "电极温度03";
CM_ SG_ 2400644704 CSC_Tpole_04_32 "电极温度04";
CM_ SG_ 2400644704 CSC_Tpole_05_32 "电极温度05";
CM_ SG_ 2400644704 CSC_Tpole_06_32 "电极温度06";
CM_ SG_ 2400644705 CSC_Tpole_No_33 "CSC号";
CM_ SG_ 2400644705 CSC_Tpole_Frame_Index_33 "当前CSC中温度数据帧序号";
CM_ SG_ 2400644705 CSC_Tpole_01_33 "电极温度01";
CM_ SG_ 2400644705 CSC_Tpole_02_33 "电极温度02";
CM_ SG_ 2400644705 CSC_Tpole_03_33 "电极温度03";
CM_ SG_ 2400644705 CSC_Tpole_04_33 "电极温度04";
CM_ SG_ 2400644705 CSC_Tpole_05_33 "电极温度05";
CM_ SG_ 2400644705 CSC_Tpole_06_33 "电极温度06";
CM_ SG_ 2400644706 CSC_Tpole_No_34 "CSC号";
CM_ SG_ 2400644706 CSC_Tpole_Frame_Index_34 "当前CSC中温度数据帧序号";
CM_ SG_ 2400644706 CSC_Tpole_01_34 "电极温度01";
CM_ SG_ 2400644706 CSC_Tpole_02_34 "电极温度02";
CM_ SG_ 2400644706 CSC_Tpole_03_34 "电极温度03";
CM_ SG_ 2400644706 CSC_Tpole_04_34 "电极温度04";
CM_ SG_ 2400644706 CSC_Tpole_05_34 "电极温度05";
CM_ SG_ 2400644706 CSC_Tpole_06_34 "电极温度06";
CM_ SG_ 2400644707 CSC_Tpole_No_35 "CSC号";
CM_ SG_ 2400644707 CSC_Tpole_Frame_Index_35 "当前CSC中温度数据帧序号";
CM_ SG_ 2400644707 CSC_Tpole_01_35 "电极温度01";
CM_ SG_ 2400644707 CSC_Tpole_02_35 "电极温度02";
CM_ SG_ 2400644707 CSC_Tpole_03_35 "电极温度03";
CM_ SG_ 2400644707 CSC_Tpole_04_35 "电极温度04";
CM_ SG_ 2400644707 CSC_Tpole_05_35 "电极温度05";
CM_ SG_ 2400644707 CSC_Tpole_06_35 "电极温度06";
CM_ SG_ 2400644708 CSC_Tpole_No_36 "CSC号";
CM_ SG_ 2400644708 CSC_Tpole_Frame_Index_36 "当前CSC中温度数据帧序号";
CM_ SG_ 2400644708 CSC_Tpole_01_36 "电极温度01";
CM_ SG_ 2400644708 CSC_Tpole_02_36 "电极温度02";
CM_ SG_ 2400644708 CSC_Tpole_03_36 "电极温度03";
CM_ SG_ 2400644708 CSC_Tpole_04_36 "电极温度04";
CM_ SG_ 2400644708 CSC_Tpole_05_36 "电极温度05";
CM_ SG_ 2400644708 CSC_Tpole_06_36 "电极温度06";
CM_ SG_ 2400644709 CSC_Tpole_No_37 "CSC号";
CM_ SG_ 2400644709 CSC_Tpole_Frame_Index_37 "当前CSC中温度数据帧序号";
CM_ SG_ 2400644709 CSC_Tpole_01_37 "电极温度01";
CM_ SG_ 2400644709 CSC_Tpole_02_37 "电极温度02";
CM_ SG_ 2400644709 CSC_Tpole_03_37 "电极温度03";
CM_ SG_ 2400644709 CSC_Tpole_04_37 "电极温度04";
CM_ SG_ 2400644709 CSC_Tpole_05_37 "电极温度05";
CM_ SG_ 2400644709 CSC_Tpole_06_37 "电极温度06";
CM_ SG_ 2400644710 CSC_Tpole_No_38 "CSC号";
CM_ SG_ 2400644710 CSC_Tpole_Frame_Index_38 "当前CSC中温度数据帧序号";
CM_ SG_ 2400644710 CSC_Tpole_01_38 "电极温度01";
CM_ SG_ 2400644710 CSC_Tpole_02_38 "电极温度02";
CM_ SG_ 2400644710 CSC_Tpole_03_38 "电极温度03";
CM_ SG_ 2400644710 CSC_Tpole_04_38 "电极温度04";
CM_ SG_ 2400644710 CSC_Tpole_05_38 "电极温度05";
CM_ SG_ 2400644710 CSC_Tpole_06_38 "电极温度06";
CM_ SG_ 2400644711 CSC_Tpole_No_39 "CSC号";
CM_ SG_ 2400644711 CSC_Tpole_Frame_Index_39 "当前CSC中温度数据帧序号";
CM_ SG_ 2400644711 CSC_Tpole_01_39 "电极温度01";
CM_ SG_ 2400644711 CSC_Tpole_02_39 "电极温度02";
CM_ SG_ 2400644711 CSC_Tpole_03_39 "电极温度03";
CM_ SG_ 2400644711 CSC_Tpole_04_39 "电极温度04";
CM_ SG_ 2400644711 CSC_Tpole_05_39 "电极温度05";
CM_ SG_ 2400644711 CSC_Tpole_06_39 "电极温度06";
CM_ SG_ 2400644712 CSC_Tpole_No_40 "CSC号";
CM_ SG_ 2400644712 CSC_Tpole_Frame_Index_40 "当前CSC中温度数据帧序号";
CM_ SG_ 2400644712 CSC_Tpole_01_40 "电极温度01";
CM_ SG_ 2400644712 CSC_Tpole_02_40 "电极温度02";
CM_ SG_ 2400644712 CSC_Tpole_03_40 "电极温度03";
CM_ SG_ 2400644712 CSC_Tpole_04_40 "电极温度04";
CM_ SG_ 2400644712 CSC_Tpole_05_40 "电极温度05";
CM_ SG_ 2400644712 CSC_Tpole_06_40 "电极温度06";
CM_ SG_ 2400644713 CSC_Tpole_No_41 "CSC号";
CM_ SG_ 2400644713 CSC_Tpole_Frame_Index_41 "当前CSC中温度数据帧序号";
CM_ SG_ 2400644713 CSC_Tpole_01_41 "电极温度01";
CM_ SG_ 2400644713 CSC_Tpole_02_41 "电极温度02";
CM_ SG_ 2400644713 CSC_Tpole_03_41 "电极温度03";
CM_ SG_ 2400644713 CSC_Tpole_04_41 "电极温度04";
CM_ SG_ 2400644713 CSC_Tpole_05_41 "电极温度05";
CM_ SG_ 2400644713 CSC_Tpole_06_41 "电极温度06";
CM_ SG_ 2400644714 CSC_Tpole_No_42 "CSC号";
CM_ SG_ 2400644714 CSC_Tpole_Frame_Index_42 "当前CSC中温度数据帧序号";
CM_ SG_ 2400644714 CSC_Tpole_01_42 "电极温度01";
CM_ SG_ 2400644714 CSC_Tpole_02_42 "电极温度02";
CM_ SG_ 2400644714 CSC_Tpole_03_42 "电极温度03";
CM_ SG_ 2400644714 CSC_Tpole_04_42 "电极温度04";
CM_ SG_ 2400644714 CSC_Tpole_05_42 "电极温度05";
CM_ SG_ 2400644714 CSC_Tpole_06_42 "电极温度06";
CM_ SG_ 2400644715 CSC_Tpole_No_43 "CSC号";
CM_ SG_ 2400644715 CSC_Tpole_Frame_Index_43 "当前CSC中温度数据帧序号";
CM_ SG_ 2400644715 CSC_Tpole_01_43 "电极温度01";
CM_ SG_ 2400644715 CSC_Tpole_02_43 "电极温度02";
CM_ SG_ 2400644715 CSC_Tpole_03_43 "电极温度03";
CM_ SG_ 2400644715 CSC_Tpole_04_43 "电极温度04";
CM_ SG_ 2400644715 CSC_Tpole_05_43 "电极温度05";
CM_ SG_ 2400644715 CSC_Tpole_06_43 "电极温度06";
CM_ SG_ 2400644716 CSC_Tpole_No_44 "CSC号";
CM_ SG_ 2400644716 CSC_Tpole_Frame_Index_44 "当前CSC中温度数据帧序号";
CM_ SG_ 2400644716 CSC_Tpole_01_44 "电极温度01";
CM_ SG_ 2400644716 CSC_Tpole_02_44 "电极温度02";
CM_ SG_ 2400644716 CSC_Tpole_03_44 "电极温度03";
CM_ SG_ 2400644716 CSC_Tpole_04_44 "电极温度04";
CM_ SG_ 2400644716 CSC_Tpole_05_44 "电极温度05";
CM_ SG_ 2400644716 CSC_Tpole_06_44 "电极温度06";
CM_ SG_ 2400644717 CSC_Tpole_No_45 "CSC号";
CM_ SG_ 2400644717 CSC_Tpole_Frame_Index_45 "当前CSC中温度数据帧序号";
CM_ SG_ 2400644717 CSC_Tpole_01_45 "电极温度01";
CM_ SG_ 2400644717 CSC_Tpole_02_45 "电极温度02";
CM_ SG_ 2400644717 CSC_Tpole_03_45 "电极温度03";
CM_ SG_ 2400644717 CSC_Tpole_04_45 "电极温度04";
CM_ SG_ 2400644717 CSC_Tpole_05_45 "电极温度05";
CM_ SG_ 2400644717 CSC_Tpole_06_45 "电极温度06";
CM_ SG_ 2400644718 CSC_Tpole_No_46 "CSC号";
CM_ SG_ 2400644718 CSC_Tpole_Frame_Index_46 "当前CSC中温度数据帧序号";
CM_ SG_ 2400644718 CSC_Tpole_01_46 "电极温度01";
CM_ SG_ 2400644718 CSC_Tpole_02_46 "电极温度02";
CM_ SG_ 2400644718 CSC_Tpole_03_46 "电极温度03";
CM_ SG_ 2400644718 CSC_Tpole_04_46 "电极温度04";
CM_ SG_ 2400644718 CSC_Tpole_05_46 "电极温度05";
CM_ SG_ 2400644718 CSC_Tpole_06_46 "电极温度06";
CM_ SG_ 2400644719 CSC_Tpole_No_47 "CSC号";
CM_ SG_ 2400644719 CSC_Tpole_Frame_Index_47 "当前CSC中温度数据帧序号";
CM_ SG_ 2400644719 CSC_Tpole_01_47 "电极温度01";
CM_ SG_ 2400644719 CSC_Tpole_02_47 "电极温度02";
CM_ SG_ 2400644719 CSC_Tpole_03_47 "电极温度03";
CM_ SG_ 2400644719 CSC_Tpole_04_47 "电极温度04";
CM_ SG_ 2400644719 CSC_Tpole_05_47 "电极温度05";
CM_ SG_ 2400644719 CSC_Tpole_06_47 "电极温度06";
CM_ SG_ 2400644720 CSC_Tpole_No_48 "CSC号";
CM_ SG_ 2400644720 CSC_Tpole_Frame_Index_48 "当前CSC中温度数据帧序号";
CM_ SG_ 2400644720 CSC_Tpole_01_48 "电极温度01";
CM_ SG_ 2400644720 CSC_Tpole_02_48 "电极温度02";
CM_ SG_ 2400644720 CSC_Tpole_03_48 "电极温度03";
CM_ SG_ 2400644720 CSC_Tpole_04_48 "电极温度04";
CM_ SG_ 2400644720 CSC_Tpole_05_48 "电极温度05";
CM_ SG_ 2400644720 CSC_Tpole_06_48 "电极温度06";
CM_ SG_ 2400644721 CSC_Tpole_No_49 "CSC号";
CM_ SG_ 2400644721 CSC_Tpole_Frame_Index_49 "当前CSC中温度数据帧序号";
CM_ SG_ 2400644721 CSC_Tpole_01_49 "电极温度01";
CM_ SG_ 2400644721 CSC_Tpole_02_49 "电极温度02";
CM_ SG_ 2400644721 CSC_Tpole_03_49 "电极温度03";
CM_ SG_ 2400644721 CSC_Tpole_04_49 "电极温度04";
CM_ SG_ 2400644721 CSC_Tpole_05_49 "电极温度05";
CM_ SG_ 2400644721 CSC_Tpole_06_49 "电极温度06";
CM_ SG_ 2400644722 CSC_Tpole_No_50 "CSC号";
CM_ SG_ 2400644722 CSC_Tpole_Frame_Index_50 "当前CSC中温度数据帧序号";
CM_ SG_ 2400644722 CSC_Tpole_01_50 "电极温度01";
CM_ SG_ 2400644722 CSC_Tpole_02_50 "电极温度02";
CM_ SG_ 2400644722 CSC_Tpole_03_50 "电极温度03";
CM_ SG_ 2400644722 CSC_Tpole_04_50 "电极温度04";
CM_ SG_ 2400644722 CSC_Tpole_05_50 "电极温度05";
CM_ SG_ 2400644722 CSC_Tpole_06_50 "电极温度06";
CM_ SG_ 2400644723 CSC_Tpole_No_51 "CSC号";
CM_ SG_ 2400644723 CSC_Tpole_Frame_Index_51 "当前CSC中温度数据帧序号";
CM_ SG_ 2400644723 CSC_Tpole_01_51 "电极温度01";
CM_ SG_ 2400644723 CSC_Tpole_02_51 "电极温度02";
CM_ SG_ 2400644723 CSC_Tpole_03_51 "电极温度03";
CM_ SG_ 2400644723 CSC_Tpole_04_51 "电极温度04";
CM_ SG_ 2400644723 CSC_Tpole_05_51 "电极温度05";
CM_ SG_ 2400644723 CSC_Tpole_06_51 "电极温度06";
CM_ SG_ 2400644724 CSC_Tpole_No_52 "CSC号";
CM_ SG_ 2400644724 CSC_Tpole_Frame_Index_52 "当前CSC中温度数据帧序号";
CM_ SG_ 2400644724 CSC_Tpole_01_52 "电极温度01";
CM_ SG_ 2400644724 CSC_Tpole_02_52 "电极温度02";
CM_ SG_ 2400644724 CSC_Tpole_03_52 "电极温度03";
CM_ SG_ 2400644724 CSC_Tpole_04_52 "电极温度04";
CM_ SG_ 2400644724 CSC_Tpole_05_52 "电极温度05";
CM_ SG_ 2400644724 CSC_Tpole_06_52 "电极温度06";
CM_ SG_ 2400644725 CSC_Tpole_No_53 "CSC号";
CM_ SG_ 2400644725 CSC_Tpole_Frame_Index_53 "当前CSC中温度数据帧序号";
CM_ SG_ 2400644725 CSC_Tpole_01_53 "电极温度01";
CM_ SG_ 2400644725 CSC_Tpole_02_53 "电极温度02";
CM_ SG_ 2400644725 CSC_Tpole_03_53 "电极温度03";
CM_ SG_ 2400644725 CSC_Tpole_04_53 "电极温度04";
CM_ SG_ 2400644725 CSC_Tpole_05_53 "电极温度05";
CM_ SG_ 2400644725 CSC_Tpole_06_53 "电极温度06";
CM_ SG_ 2400644726 CSC_Tpole_No_54 "CSC号";
CM_ SG_ 2400644726 CSC_Tpole_Frame_Index_54 "当前CSC中温度数据帧序号";
CM_ SG_ 2400644726 CSC_Tpole_01_54 "电极温度01";
CM_ SG_ 2400644726 CSC_Tpole_02_54 "电极温度02";
CM_ SG_ 2400644726 CSC_Tpole_03_54 "电极温度03";
CM_ SG_ 2400644726 CSC_Tpole_04_54 "电极温度04";
CM_ SG_ 2400644726 CSC_Tpole_05_54 "电极温度05";
CM_ SG_ 2400644726 CSC_Tpole_06_54 "电极温度06";
CM_ SG_ 2400644727 CSC_Tpole_No_55 "CSC号";
CM_ SG_ 2400644727 CSC_Tpole_Frame_Index_55 "当前CSC中温度数据帧序号";
CM_ SG_ 2400644727 CSC_Tpole_01_55 "电极温度01";
CM_ SG_ 2400644727 CSC_Tpole_02_55 "电极温度02";
CM_ SG_ 2400644727 CSC_Tpole_03_55 "电极温度03";
CM_ SG_ 2400644727 CSC_Tpole_04_55 "电极温度04";
CM_ SG_ 2400644727 CSC_Tpole_05_55 "电极温度05";
CM_ SG_ 2400644727 CSC_Tpole_06_55 "电极温度06";
CM_ SG_ 2400644728 CSC_Tpole_No_56 "CSC号";
CM_ SG_ 2400644728 CSC_Tpole_Frame_Index_56 "当前CSC中温度数据帧序号";
CM_ SG_ 2400644728 CSC_Tpole_01_56 "电极温度01";
CM_ SG_ 2400644728 CSC_Tpole_02_56 "电极温度02";
CM_ SG_ 2400644728 CSC_Tpole_03_56 "电极温度03";
CM_ SG_ 2400644728 CSC_Tpole_04_56 "电极温度04";
CM_ SG_ 2400644728 CSC_Tpole_05_56 "电极温度05";
CM_ SG_ 2400644728 CSC_Tpole_06_56 "电极温度06";
CM_ SG_ 2400644729 CSC_Tpole_No_57 "CSC号";
CM_ SG_ 2400644729 CSC_Tpole_Frame_Index_57 "当前CSC中温度数据帧序号";
CM_ SG_ 2400644729 CSC_Tpole_01_57 "电极温度01";
CM_ SG_ 2400644729 CSC_Tpole_02_57 "电极温度02";
CM_ SG_ 2400644729 CSC_Tpole_03_57 "电极温度03";
CM_ SG_ 2400644729 CSC_Tpole_04_57 "电极温度04";
CM_ SG_ 2400644729 CSC_Tpole_05_57 "电极温度05";
CM_ SG_ 2400644729 CSC_Tpole_06_57 "电极温度06";
CM_ SG_ 2400644730 CSC_Tpole_No_58 "CSC号";
CM_ SG_ 2400644730 CSC_Tpole_Frame_Index_58 "当前CSC中温度数据帧序号";
CM_ SG_ 2400644730 CSC_Tpole_01_58 "电极温度01";
CM_ SG_ 2400644730 CSC_Tpole_02_58 "电极温度02";
CM_ SG_ 2400644730 CSC_Tpole_03_58 "电极温度03";
CM_ SG_ 2400644730 CSC_Tpole_04_58 "电极温度04";
CM_ SG_ 2400644730 CSC_Tpole_05_58 "电极温度05";
CM_ SG_ 2400644730 CSC_Tpole_06_58 "电极温度06";
CM_ SG_ 2400644731 CSC_Tpole_No_59 "CSC号";
CM_ SG_ 2400644731 CSC_Tpole_Frame_Index_59 "当前CSC中温度数据帧序号";
CM_ SG_ 2400644731 CSC_Tpole_01_59 "电极温度01";
CM_ SG_ 2400644731 CSC_Tpole_02_59 "电极温度02";
CM_ SG_ 2400644731 CSC_Tpole_03_59 "电极温度03";
CM_ SG_ 2400644731 CSC_Tpole_04_59 "电极温度04";
CM_ SG_ 2400644731 CSC_Tpole_05_59 "电极温度05";
CM_ SG_ 2400644731 CSC_Tpole_06_59 "电极温度06";
CM_ SG_ 2400644732 CSC_Tpole_No_60 "CSC号";
CM_ SG_ 2400644732 CSC_Tpole_Frame_Index_60 "当前CSC中温度数据帧序号";
CM_ SG_ 2400644732 CSC_Tpole_01_60 "电极温度01";
CM_ SG_ 2400644732 CSC_Tpole_02_60 "电极温度02";
CM_ SG_ 2400644732 CSC_Tpole_03_60 "电极温度03";
CM_ SG_ 2400644732 CSC_Tpole_04_60 "电极温度04";
CM_ SG_ 2400644732 CSC_Tpole_05_60 "电极温度05";
CM_ SG_ 2400644732 CSC_Tpole_06_60 "电极温度06";
CM_ SG_ 2400644733 CSC_Tpole_No_61 "CSC号";
CM_ SG_ 2400644733 CSC_Tpole_Frame_Index_61 "当前CSC中温度数据帧序号";
CM_ SG_ 2400644733 CSC_Tpole_01_61 "电极温度01";
CM_ SG_ 2400644733 CSC_Tpole_02_61 "电极温度02";
CM_ SG_ 2400644733 CSC_Tpole_03_61 "电极温度03";
CM_ SG_ 2400644733 CSC_Tpole_04_61 "电极温度04";
CM_ SG_ 2400644733 CSC_Tpole_05_61 "电极温度05";
CM_ SG_ 2400644733 CSC_Tpole_06_61 "电极温度06";
CM_ SG_ 2400644734 CSC_Tpole_No_62 "CSC号";
CM_ SG_ 2400644734 CSC_Tpole_Frame_Index_62 "当前CSC中温度数据帧序号";
CM_ SG_ 2400644734 CSC_Tpole_01_62 "电极温度01";
CM_ SG_ 2400644734 CSC_Tpole_02_62 "电极温度02";
CM_ SG_ 2400644734 CSC_Tpole_03_62 "电极温度03";
CM_ SG_ 2400644734 CSC_Tpole_04_62 "电极温度04";
CM_ SG_ 2400644734 CSC_Tpole_05_62 "电极温度05";
CM_ SG_ 2400644734 CSC_Tpole_06_62 "电极温度06";
CM_ SG_ 2400644735 CSC_Tpole_No_63 "CSC号";
CM_ SG_ 2400644735 CSC_Tpole_Frame_Index_63 "当前CSC中温度数据帧序号";
CM_ SG_ 2400644735 CSC_Tpole_01_63 "电极温度01";
CM_ SG_ 2400644735 CSC_Tpole_02_63 "电极温度02";
CM_ SG_ 2400644735 CSC_Tpole_03_63 "电极温度03";
CM_ SG_ 2400644735 CSC_Tpole_04_63 "电极温度04";
CM_ SG_ 2400644735 CSC_Tpole_05_63 "电极温度05";
CM_ SG_ 2400644735 CSC_Tpole_06_63 "电极温度06";
CM_ SG_ 2332618385 M2P_SysMaxVolt_HvOn_01 "系统所有高压在线的电柜的单体最大电压  ";
CM_ SG_ 2332618385 M2P_SysMinVolt_HvOn_01 "系统所有高压在线的电柜的单体最小电压  ";
CM_ SG_ 2332618385 M2P_SysAvgVolt_HvOn_01 "系统所有高压在线的电柜的单体平均电压  ";
CM_ SG_ 2332618386 M2P_SysMaxVolt_HvOn_02 "系统所有高压在线的电柜的单体最大电压  ";
CM_ SG_ 2332618386 M2P_SysMinVolt_HvOn_02 "系统所有高压在线的电柜的单体最小电压  ";
CM_ SG_ 2332618386 M2P_SysAvgVolt_HvOn_02 "系统所有高压在线的电柜的单体平均电压  ";
CM_ SG_ 2332618387 M2P_SysMaxVolt_HvOn_03 "系统所有高压在线的电柜的单体最大电压  ";
CM_ SG_ 2332618387 M2P_SysMinVolt_HvOn_03 "系统所有高压在线的电柜的单体最小电压  ";
CM_ SG_ 2332618387 M2P_SysAvgVolt_HvOn_03 "系统所有高压在线的电柜的单体平均电压  ";
CM_ SG_ 2332618388 M2P_SysMaxVolt_HvOn_04 "系统所有高压在线的电柜的单体最大电压  ";
CM_ SG_ 2332618388 M2P_SysMinVolt_HvOn_04 "系统所有高压在线的电柜的单体最小电压  ";
CM_ SG_ 2332618388 M2P_SysAvgVolt_HvOn_04 "系统所有高压在线的电柜的单体平均电压  ";
CM_ SG_ 2332618389 M2P_SysMaxVolt_HvOn_05 "系统所有高压在线的电柜的单体最大电压  ";
CM_ SG_ 2332618389 M2P_SysMinVolt_HvOn_05 "系统所有高压在线的电柜的单体最小电压  ";
CM_ SG_ 2332618389 M2P_SysAvgVolt_HvOn_05 "系统所有高压在线的电柜的单体平均电压  ";
CM_ SG_ 2332618390 M2P_SysMaxVolt_HvOn_06 "系统所有高压在线的电柜的单体最大电压  ";
CM_ SG_ 2332618390 M2P_SysMinVolt_HvOn_06 "系统所有高压在线的电柜的单体最小电压  ";
CM_ SG_ 2332618390 M2P_SysAvgVolt_HvOn_06 "系统所有高压在线的电柜的单体平均电压  ";
CM_ SG_ 2332618391 M2P_SysMaxVolt_HvOn_07 "系统所有高压在线的电柜的单体最大电压  ";
CM_ SG_ 2332618391 M2P_SysMinVolt_HvOn_07 "系统所有高压在线的电柜的单体最小电压  ";
CM_ SG_ 2332618391 M2P_SysAvgVolt_HvOn_07 "系统所有高压在线的电柜的单体平均电压  ";
CM_ SG_ 2332618392 M2P_SysMaxVolt_HvOn_08 "系统所有高压在线的电柜的单体最大电压  ";
CM_ SG_ 2332618392 M2P_SysMinVolt_HvOn_08 "系统所有高压在线的电柜的单体最小电压  ";
CM_ SG_ 2332618392 M2P_SysAvgVolt_HvOn_08 "系统所有高压在线的电柜的单体平均电压  ";
CM_ SG_ 2332618393 M2P_SysMaxVolt_HvOn_09 "系统所有高压在线的电柜的单体最大电压  ";
CM_ SG_ 2332618393 M2P_SysMinVolt_HvOn_09 "系统所有高压在线的电柜的单体最小电压  ";
CM_ SG_ 2332618393 M2P_SysAvgVolt_HvOn_09 "系统所有高压在线的电柜的单体平均电压  ";
CM_ SG_ 2332618394 M2P_SysMaxVolt_HvOn_10 "系统所有高压在线的电柜的单体最大电压  ";
CM_ SG_ 2332618394 M2P_SysMinVolt_HvOn_10 "系统所有高压在线的电柜的单体最小电压  ";
CM_ SG_ 2332618394 M2P_SysAvgVolt_HvOn_10 "系统所有高压在线的电柜的单体平均电压  ";
CM_ SG_ 2332618395 M2P_SysMaxVolt_HvOn_11 "系统所有高压在线的电柜的单体最大电压  ";
CM_ SG_ 2332618395 M2P_SysMinVolt_HvOn_11 "系统所有高压在线的电柜的单体最小电压  ";
CM_ SG_ 2332618395 M2P_SysAvgVolt_HvOn_11 "系统所有高压在线的电柜的单体平均电压  ";
CM_ SG_ 2332618396 M2P_SysMaxVolt_HvOn_12 "系统所有高压在线的电柜的单体最大电压  ";
CM_ SG_ 2332618396 M2P_SysMinVolt_HvOn_12 "系统所有高压在线的电柜的单体最小电压  ";
CM_ SG_ 2332618396 M2P_SysAvgVolt_HvOn_12 "系统所有高压在线的电柜的单体平均电压  ";
CM_ SG_ 2332618397 M2P_SysMaxVolt_HvOn_13 "系统所有高压在线的电柜的单体最大电压  ";
CM_ SG_ 2332618397 M2P_SysMinVolt_HvOn_13 "系统所有高压在线的电柜的单体最小电压  ";
CM_ SG_ 2332618397 M2P_SysAvgVolt_HvOn_13 "系统所有高压在线的电柜的单体平均电压  ";
CM_ SG_ 2332618398 M2P_SysMaxVolt_HvOn_14 "系统所有高压在线的电柜的单体最大电压  ";
CM_ SG_ 2332618398 M2P_SysMinVolt_HvOn_14 "系统所有高压在线的电柜的单体最小电压  ";
CM_ SG_ 2332618398 M2P_SysAvgVolt_HvOn_14 "系统所有高压在线的电柜的单体平均电压  ";
CM_ SG_ 2332618399 M2P_SysMaxVolt_HvOn_15 "系统所有高压在线的电柜的单体最大电压  ";
CM_ SG_ 2332618399 M2P_SysMinVolt_HvOn_15 "系统所有高压在线的电柜的单体最小电压  ";
CM_ SG_ 2332618399 M2P_SysAvgVolt_HvOn_15 "系统所有高压在线的电柜的单体平均电压  ";
CM_ SG_ 2332618400 M2P_SysMaxVolt_HvOn_16 "系统所有高压在线的电柜的单体最大电压  ";
CM_ SG_ 2332618400 M2P_SysMinVolt_HvOn_16 "系统所有高压在线的电柜的单体最小电压  ";
CM_ SG_ 2332618400 M2P_SysAvgVolt_HvOn_16 "系统所有高压在线的电柜的单体平均电压  ";
CM_ SG_ 2332618401 M2P_SysMaxVolt_HvOn_17 "系统所有高压在线的电柜的单体最大电压  ";
CM_ SG_ 2332618401 M2P_SysMinVolt_HvOn_17 "系统所有高压在线的电柜的单体最小电压  ";
CM_ SG_ 2332618401 M2P_SysAvgVolt_HvOn_17 "系统所有高压在线的电柜的单体平均电压  ";
CM_ SG_ 2332618402 M2P_SysMaxVolt_HvOn_18 "系统所有高压在线的电柜的单体最大电压  ";
CM_ SG_ 2332618402 M2P_SysMinVolt_HvOn_18 "系统所有高压在线的电柜的单体最小电压  ";
CM_ SG_ 2332618402 M2P_SysAvgVolt_HvOn_18 "系统所有高压在线的电柜的单体平均电压  ";
CM_ SG_ 2332618403 M2P_SysMaxVolt_HvOn_19 "系统所有高压在线的电柜的单体最大电压  ";
CM_ SG_ 2332618403 M2P_SysMinVolt_HvOn_19 "系统所有高压在线的电柜的单体最小电压  ";
CM_ SG_ 2332618403 M2P_SysAvgVolt_HvOn_19 "系统所有高压在线的电柜的单体平均电压  ";
CM_ SG_ 2332618404 M2P_SysMaxVolt_HvOn_20 "系统所有高压在线的电柜的单体最大电压  ";
CM_ SG_ 2332618404 M2P_SysMinVolt_HvOn_20 "系统所有高压在线的电柜的单体最小电压  ";
CM_ SG_ 2332618404 M2P_SysAvgVolt_HvOn_20 "系统所有高压在线的电柜的单体平均电压  ";
CM_ SG_ 2332618405 M2P_SysMaxVolt_HvOn_21 "系统所有高压在线的电柜的单体最大电压  ";
CM_ SG_ 2332618405 M2P_SysMinVolt_HvOn_21 "系统所有高压在线的电柜的单体最小电压  ";
CM_ SG_ 2332618405 M2P_SysAvgVolt_HvOn_21 "系统所有高压在线的电柜的单体平均电压  ";
CM_ SG_ 2332618406 M2P_SysMaxVolt_HvOn_22 "系统所有高压在线的电柜的单体最大电压  ";
CM_ SG_ 2332618406 M2P_SysMinVolt_HvOn_22 "系统所有高压在线的电柜的单体最小电压  ";
CM_ SG_ 2332618406 M2P_SysAvgVolt_HvOn_22 "系统所有高压在线的电柜的单体平均电压  ";
CM_ SG_ 2332618407 M2P_SysMaxVolt_HvOn_23 "系统所有高压在线的电柜的单体最大电压  ";
CM_ SG_ 2332618407 M2P_SysMinVolt_HvOn_23 "系统所有高压在线的电柜的单体最小电压  ";
CM_ SG_ 2332618407 M2P_SysAvgVolt_HvOn_23 "系统所有高压在线的电柜的单体平均电压  ";
CM_ SG_ 2332618408 M2P_SysMaxVolt_HvOn_24 "系统所有高压在线的电柜的单体最大电压  ";
CM_ SG_ 2332618408 M2P_SysMinVolt_HvOn_24 "系统所有高压在线的电柜的单体最小电压  ";
CM_ SG_ 2332618408 M2P_SysAvgVolt_HvOn_24 "系统所有高压在线的电柜的单体平均电压  ";
CM_ SG_ 2332618409 M2P_SysMaxVolt_HvOn_25 "系统所有高压在线的电柜的单体最大电压  ";
CM_ SG_ 2332618409 M2P_SysMinVolt_HvOn_25 "系统所有高压在线的电柜的单体最小电压  ";
CM_ SG_ 2332618409 M2P_SysAvgVolt_HvOn_25 "系统所有高压在线的电柜的单体平均电压  ";
CM_ SG_ 2332618410 M2P_SysMaxVolt_HvOn_26 "系统所有高压在线的电柜的单体最大电压  ";
CM_ SG_ 2332618410 M2P_SysMinVolt_HvOn_26 "系统所有高压在线的电柜的单体最小电压  ";
CM_ SG_ 2332618410 M2P_SysAvgVolt_HvOn_26 "系统所有高压在线的电柜的单体平均电压  ";
CM_ SG_ 2332618411 M2P_SysMaxVolt_HvOn_27 "系统所有高压在线的电柜的单体最大电压  ";
CM_ SG_ 2332618411 M2P_SysMinVolt_HvOn_27 "系统所有高压在线的电柜的单体最小电压  ";
CM_ SG_ 2332618411 M2P_SysAvgVolt_HvOn_27 "系统所有高压在线的电柜的单体平均电压  ";
CM_ SG_ 2332618412 M2P_SysMaxVolt_HvOn_28 "系统所有高压在线的电柜的单体最大电压  ";
CM_ SG_ 2332618412 M2P_SysMinVolt_HvOn_28 "系统所有高压在线的电柜的单体最小电压  ";
CM_ SG_ 2332618412 M2P_SysAvgVolt_HvOn_28 "系统所有高压在线的电柜的单体平均电压  ";
CM_ SG_ 2332618413 M2P_SysMaxVolt_HvOn_29 "系统所有高压在线的电柜的单体最大电压  ";
CM_ SG_ 2332618413 M2P_SysMinVolt_HvOn_29 "系统所有高压在线的电柜的单体最小电压  ";
CM_ SG_ 2332618413 M2P_SysAvgVolt_HvOn_29 "系统所有高压在线的电柜的单体平均电压  ";
CM_ SG_ 2332618414 M2P_SysMaxVolt_HvOn_30 "系统所有高压在线的电柜的单体最大电压  ";
CM_ SG_ 2332618414 M2P_SysMinVolt_HvOn_30 "系统所有高压在线的电柜的单体最小电压  ";
CM_ SG_ 2332618414 M2P_SysAvgVolt_HvOn_30 "系统所有高压在线的电柜的单体平均电压  ";
CM_ SG_ 2332618415 M2P_SysMaxVolt_HvOn_31 "系统所有高压在线的电柜的单体最大电压  ";
CM_ SG_ 2332618415 M2P_SysMinVolt_HvOn_31 "系统所有高压在线的电柜的单体最小电压  ";
CM_ SG_ 2332618415 M2P_SysAvgVolt_HvOn_31 "系统所有高压在线的电柜的单体平均电压  ";
CM_ SG_ 2332683921 M2P_SysMaxTemp_HvOn01 "系统所有高压在线的电柜的最大电芯温度";
CM_ SG_ 2332683921 M2P_SysMinTemp_HvOn01 "系统所有高压在线的电柜的最小电芯温度";
CM_ SG_ 2332683921 M2P_SysAvgTemp_HvOn01 "系统所有高压在线的电柜的平均电芯温度";
CM_ SG_ 2332683921 M2P_SbmuPst_SysMaxTemp_HvOn01 "系统所有高压在线的电柜的最大电芯温度所处SBMU编号";
CM_ SG_ 2332683921 M2P_CscPst_SysMaxTemp_HvOn01 "系统所有高压在线的电柜的最大电芯温度所处CSC编号";
CM_ SG_ 2332683921 M2P_SbmuPst_SysMinTemp_HvOn01 "系统所有高压在线的电柜的最小电芯温度所处SBMU编号";
CM_ SG_ 2332683921 M2P_CscPst_SysMinTemp_HvOn01 "系统所有高压在线的电柜的最小电芯温度所处CSC编号";
CM_ SG_ 2332683922 M2P_SysMaxTemp_HvOn02 "系统所有高压在线的电柜的最大电芯温度";
CM_ SG_ 2332683922 M2P_SysMinTemp_HvOn02 "系统所有高压在线的电柜的最小电芯温度";
CM_ SG_ 2332683922 M2P_SysAvgTemp_HvOn02 "系统所有高压在线的电柜的平均电芯温度";
CM_ SG_ 2332683922 M2P_SbmuPst_SysMaxTemp_HvOn02 "系统所有高压在线的电柜的最大电芯温度所处SBMU编号";
CM_ SG_ 2332683922 M2P_CscPst_SysMaxTemp_HvOn02 "系统所有高压在线的电柜的最大电芯温度所处CSC编号";
CM_ SG_ 2332683922 M2P_SbmuPst_SysMinTemp_HvOn02 "系统所有高压在线的电柜的最小电芯温度所处SBMU编号";
CM_ SG_ 2332683922 M2P_CscPst_SysMinTemp_HvOn02 "系统所有高压在线的电柜的最小电芯温度所处CSC编号";
CM_ SG_ 2332683923 M2P_SysMaxTemp_HvOn03 "系统所有高压在线的电柜的最大电芯温度";
CM_ SG_ 2332683923 M2P_SysMinTemp_HvOn03 "系统所有高压在线的电柜的最小电芯温度";
CM_ SG_ 2332683923 M2P_SysAvgTemp_HvOn03 "系统所有高压在线的电柜的平均电芯温度";
CM_ SG_ 2332683923 M2P_SbmuPst_SysMaxTemp_HvOn03 "系统所有高压在线的电柜的最大电芯温度所处SBMU编号";
CM_ SG_ 2332683923 M2P_CscPst_SysMaxTemp_HvOn03 "系统所有高压在线的电柜的最大电芯温度所处CSC编号";
CM_ SG_ 2332683923 M2P_SbmuPst_SysMinTemp_HvOn03 "系统所有高压在线的电柜的最小电芯温度所处SBMU编号";
CM_ SG_ 2332683923 M2P_CscPst_SysMinTemp_HvOn03 "系统所有高压在线的电柜的最小电芯温度所处CSC编号";
CM_ SG_ 2332683924 M2P_SysMaxTemp_HvOn04 "系统所有高压在线的电柜的最大电芯温度";
CM_ SG_ 2332683924 M2P_SysMinTemp_HvOn04 "系统所有高压在线的电柜的最小电芯温度";
CM_ SG_ 2332683924 M2P_SysAvgTemp_HvOn04 "系统所有高压在线的电柜的平均电芯温度";
CM_ SG_ 2332683924 M2P_SbmuPst_SysMaxTemp_HvOn04 "系统所有高压在线的电柜的最大电芯温度所处SBMU编号";
CM_ SG_ 2332683924 M2P_CscPst_SysMaxTemp_HvOn04 "系统所有高压在线的电柜的最大电芯温度所处CSC编号";
CM_ SG_ 2332683924 M2P_SbmuPst_SysMinTemp_HvOn04 "系统所有高压在线的电柜的最小电芯温度所处SBMU编号";
CM_ SG_ 2332683924 M2P_CscPst_SysMinTemp_HvOn04 "系统所有高压在线的电柜的最小电芯温度所处CSC编号";
CM_ SG_ 2332683925 M2P_SysMaxTemp_HvOn05 "系统所有高压在线的电柜的最大电芯温度";
CM_ SG_ 2332683925 M2P_SysMinTemp_HvOn05 "系统所有高压在线的电柜的最小电芯温度";
CM_ SG_ 2332683925 M2P_SysAvgTemp_HvOn05 "系统所有高压在线的电柜的平均电芯温度";
CM_ SG_ 2332683925 M2P_SbmuPst_SysMaxTemp_HvOn05 "系统所有高压在线的电柜的最大电芯温度所处SBMU编号";
CM_ SG_ 2332683925 M2P_CscPst_SysMaxTemp_HvOn05 "系统所有高压在线的电柜的最大电芯温度所处CSC编号";
CM_ SG_ 2332683925 M2P_SbmuPst_SysMinTemp_HvOn05 "系统所有高压在线的电柜的最小电芯温度所处SBMU编号";
CM_ SG_ 2332683925 M2P_CscPst_SysMinTemp_HvOn05 "系统所有高压在线的电柜的最小电芯温度所处CSC编号";
CM_ SG_ 2332683926 M2P_SysMaxTemp_HvOn06 "系统所有高压在线的电柜的最大电芯温度";
CM_ SG_ 2332683926 M2P_SysMinTemp_HvOn06 "系统所有高压在线的电柜的最小电芯温度";
CM_ SG_ 2332683926 M2P_SysAvgTemp_HvOn06 "系统所有高压在线的电柜的平均电芯温度";
CM_ SG_ 2332683926 M2P_SbmuPst_SysMaxTemp_HvOn06 "系统所有高压在线的电柜的最大电芯温度所处SBMU编号";
CM_ SG_ 2332683926 M2P_CscPst_SysMaxTemp_HvOn06 "系统所有高压在线的电柜的最大电芯温度所处CSC编号";
CM_ SG_ 2332683926 M2P_SbmuPst_SysMinTemp_HvOn06 "系统所有高压在线的电柜的最小电芯温度所处SBMU编号";
CM_ SG_ 2332683926 M2P_CscPst_SysMinTemp_HvOn06 "系统所有高压在线的电柜的最小电芯温度所处CSC编号";
CM_ SG_ 2332683927 M2P_SysMaxTemp_HvOn07 "系统所有高压在线的电柜的最大电芯温度";
CM_ SG_ 2332683927 M2P_SysMinTemp_HvOn07 "系统所有高压在线的电柜的最小电芯温度";
CM_ SG_ 2332683927 M2P_SysAvgTemp_HvOn07 "系统所有高压在线的电柜的平均电芯温度";
CM_ SG_ 2332683927 M2P_SbmuPst_SysMaxTemp_HvOn07 "系统所有高压在线的电柜的最大电芯温度所处SBMU编号";
CM_ SG_ 2332683927 M2P_CscPst_SysMaxTemp_HvOn07 "系统所有高压在线的电柜的最大电芯温度所处CSC编号";
CM_ SG_ 2332683927 M2P_SbmuPst_SysMinTemp_HvOn07 "系统所有高压在线的电柜的最小电芯温度所处SBMU编号";
CM_ SG_ 2332683927 M2P_CscPst_SysMinTemp_HvOn07 "系统所有高压在线的电柜的最小电芯温度所处CSC编号";
CM_ SG_ 2332683928 M2P_SysMaxTemp_HvOn08 "系统所有高压在线的电柜的最大电芯温度";
CM_ SG_ 2332683928 M2P_SysMinTemp_HvOn08 "系统所有高压在线的电柜的最小电芯温度";
CM_ SG_ 2332683928 M2P_SysAvgTemp_HvOn08 "系统所有高压在线的电柜的平均电芯温度";
CM_ SG_ 2332683928 M2P_SbmuPst_SysMaxTemp_HvOn08 "系统所有高压在线的电柜的最大电芯温度所处SBMU编号";
CM_ SG_ 2332683928 M2P_CscPst_SysMaxTemp_HvOn08 "系统所有高压在线的电柜的最大电芯温度所处CSC编号";
CM_ SG_ 2332683928 M2P_SbmuPst_SysMinTemp_HvOn08 "系统所有高压在线的电柜的最小电芯温度所处SBMU编号";
CM_ SG_ 2332683928 M2P_CscPst_SysMinTemp_HvOn08 "系统所有高压在线的电柜的最小电芯温度所处CSC编号";
CM_ SG_ 2332683929 M2P_SysMaxTemp_HvOn09 "系统所有高压在线的电柜的最大电芯温度";
CM_ SG_ 2332683929 M2P_SysMinTemp_HvOn09 "系统所有高压在线的电柜的最小电芯温度";
CM_ SG_ 2332683929 M2P_SysAvgTemp_HvOn09 "系统所有高压在线的电柜的平均电芯温度";
CM_ SG_ 2332683929 M2P_SbmuPst_SysMaxTemp_HvOn09 "系统所有高压在线的电柜的最大电芯温度所处SBMU编号";
CM_ SG_ 2332683929 M2P_CscPst_SysMaxTemp_HvOn09 "系统所有高压在线的电柜的最大电芯温度所处CSC编号";
CM_ SG_ 2332683929 M2P_SbmuPst_SysMinTemp_HvOn09 "系统所有高压在线的电柜的最小电芯温度所处SBMU编号";
CM_ SG_ 2332683929 M2P_CscPst_SysMinTemp_HvOn09 "系统所有高压在线的电柜的最小电芯温度所处CSC编号";
CM_ SG_ 2332683930 M2P_SysMaxTemp_HvOn10 "系统所有高压在线的电柜的最大电芯温度";
CM_ SG_ 2332683930 M2P_SysMinTemp_HvOn10 "系统所有高压在线的电柜的最小电芯温度";
CM_ SG_ 2332683930 M2P_SysAvgTemp_HvOn10 "系统所有高压在线的电柜的平均电芯温度";
CM_ SG_ 2332683930 M2P_SbmuPst_SysMaxTemp_HvOn10 "系统所有高压在线的电柜的最大电芯温度所处SBMU编号";
CM_ SG_ 2332683930 M2P_CscPst_SysMaxTemp_HvOn10 "系统所有高压在线的电柜的最大电芯温度所处CSC编号";
CM_ SG_ 2332683930 M2P_SbmuPst_SysMinTemp_HvOn10 "系统所有高压在线的电柜的最小电芯温度所处SBMU编号";
CM_ SG_ 2332683930 M2P_CscPst_SysMinTemp_HvOn10 "系统所有高压在线的电柜的最小电芯温度所处CSC编号";
CM_ SG_ 2332683931 M2P_SysMaxTemp_HvOn11 "系统所有高压在线的电柜的最大电芯温度";
CM_ SG_ 2332683931 M2P_SysMinTemp_HvOn11 "系统所有高压在线的电柜的最小电芯温度";
CM_ SG_ 2332683931 M2P_SysAvgTemp_HvOn11 "系统所有高压在线的电柜的平均电芯温度";
CM_ SG_ 2332683931 M2P_SbmuPst_SysMaxTemp_HvOn11 "系统所有高压在线的电柜的最大电芯温度所处SBMU编号";
CM_ SG_ 2332683931 M2P_CscPst_SysMaxTemp_HvOn11 "系统所有高压在线的电柜的最大电芯温度所处CSC编号";
CM_ SG_ 2332683931 M2P_SbmuPst_SysMinTemp_HvOn11 "系统所有高压在线的电柜的最小电芯温度所处SBMU编号";
CM_ SG_ 2332683931 M2P_CscPst_SysMinTemp_HvOn11 "系统所有高压在线的电柜的最小电芯温度所处CSC编号";
CM_ SG_ 2332683932 M2P_SysMaxTemp_HvOn12 "系统所有高压在线的电柜的最大电芯温度";
CM_ SG_ 2332683932 M2P_SysMinTemp_HvOn12 "系统所有高压在线的电柜的最小电芯温度";
CM_ SG_ 2332683932 M2P_SysAvgTemp_HvOn12 "系统所有高压在线的电柜的平均电芯温度";
CM_ SG_ 2332683932 M2P_SbmuPst_SysMaxTemp_HvOn12 "系统所有高压在线的电柜的最大电芯温度所处SBMU编号";
CM_ SG_ 2332683932 M2P_CscPst_SysMaxTemp_HvOn12 "系统所有高压在线的电柜的最大电芯温度所处CSC编号";
CM_ SG_ 2332683932 M2P_SbmuPst_SysMinTemp_HvOn12 "系统所有高压在线的电柜的最小电芯温度所处SBMU编号";
CM_ SG_ 2332683932 M2P_CscPst_SysMinTemp_HvOn12 "系统所有高压在线的电柜的最小电芯温度所处CSC编号";
CM_ SG_ 2332683933 M2P_SysMaxTemp_HvOn13 "系统所有高压在线的电柜的最大电芯温度";
CM_ SG_ 2332683933 M2P_SysMinTemp_HvOn13 "系统所有高压在线的电柜的最小电芯温度";
CM_ SG_ 2332683933 M2P_SysAvgTemp_HvOn13 "系统所有高压在线的电柜的平均电芯温度";
CM_ SG_ 2332683933 M2P_SbmuPst_SysMaxTemp_HvOn13 "系统所有高压在线的电柜的最大电芯温度所处SBMU编号";
CM_ SG_ 2332683933 M2P_CscPst_SysMaxTemp_HvOn13 "系统所有高压在线的电柜的最大电芯温度所处CSC编号";
CM_ SG_ 2332683933 M2P_SbmuPst_SysMinTemp_HvOn13 "系统所有高压在线的电柜的最小电芯温度所处SBMU编号";
CM_ SG_ 2332683933 M2P_CscPst_SysMinTemp_HvOn13 "系统所有高压在线的电柜的最小电芯温度所处CSC编号";
CM_ SG_ 2332683934 M2P_SysMaxTemp_HvOn14 "系统所有高压在线的电柜的最大电芯温度";
CM_ SG_ 2332683934 M2P_SysMinTemp_HvOn14 "系统所有高压在线的电柜的最小电芯温度";
CM_ SG_ 2332683934 M2P_SysAvgTemp_HvOn14 "系统所有高压在线的电柜的平均电芯温度";
CM_ SG_ 2332683934 M2P_SbmuPst_SysMaxTemp_HvOn14 "系统所有高压在线的电柜的最大电芯温度所处SBMU编号";
CM_ SG_ 2332683934 M2P_CscPst_SysMaxTemp_HvOn14 "系统所有高压在线的电柜的最大电芯温度所处CSC编号";
CM_ SG_ 2332683934 M2P_SbmuPst_SysMinTemp_HvOn14 "系统所有高压在线的电柜的最小电芯温度所处SBMU编号";
CM_ SG_ 2332683934 M2P_CscPst_SysMinTemp_HvOn14 "系统所有高压在线的电柜的最小电芯温度所处CSC编号";
CM_ SG_ 2332683935 M2P_SysMaxTemp_HvOn15 "系统所有高压在线的电柜的最大电芯温度";
CM_ SG_ 2332683935 M2P_SysMinTemp_HvOn15 "系统所有高压在线的电柜的最小电芯温度";
CM_ SG_ 2332683935 M2P_SysAvgTemp_HvOn15 "系统所有高压在线的电柜的平均电芯温度";
CM_ SG_ 2332683935 M2P_SbmuPst_SysMaxTemp_HvOn15 "系统所有高压在线的电柜的最大电芯温度所处SBMU编号";
CM_ SG_ 2332683935 M2P_CscPst_SysMaxTemp_HvOn15 "系统所有高压在线的电柜的最大电芯温度所处CSC编号";
CM_ SG_ 2332683935 M2P_SbmuPst_SysMinTemp_HvOn15 "系统所有高压在线的电柜的最小电芯温度所处SBMU编号";
CM_ SG_ 2332683935 M2P_CscPst_SysMinTemp_HvOn15 "系统所有高压在线的电柜的最小电芯温度所处CSC编号";
CM_ SG_ 2332683936 M2P_SysMaxTemp_HvOn16 "系统所有高压在线的电柜的最大电芯温度";
CM_ SG_ 2332683936 M2P_SysMinTemp_HvOn16 "系统所有高压在线的电柜的最小电芯温度";
CM_ SG_ 2332683936 M2P_SysAvgTemp_HvOn16 "系统所有高压在线的电柜的平均电芯温度";
CM_ SG_ 2332683936 M2P_SbmuPst_SysMaxTemp_HvOn16 "系统所有高压在线的电柜的最大电芯温度所处SBMU编号";
CM_ SG_ 2332683936 M2P_CscPst_SysMaxTemp_HvOn16 "系统所有高压在线的电柜的最大电芯温度所处CSC编号";
CM_ SG_ 2332683936 M2P_SbmuPst_SysMinTemp_HvOn16 "系统所有高压在线的电柜的最小电芯温度所处SBMU编号";
CM_ SG_ 2332683936 M2P_CscPst_SysMinTemp_HvOn16 "系统所有高压在线的电柜的最小电芯温度所处CSC编号";
CM_ SG_ 2332683937 M2P_SysMaxTemp_HvOn17 "系统所有高压在线的电柜的最大电芯温度";
CM_ SG_ 2332683937 M2P_SysMinTemp_HvOn17 "系统所有高压在线的电柜的最小电芯温度";
CM_ SG_ 2332683937 M2P_SysAvgTemp_HvOn17 "系统所有高压在线的电柜的平均电芯温度";
CM_ SG_ 2332683937 M2P_SbmuPst_SysMaxTemp_HvOn17 "系统所有高压在线的电柜的最大电芯温度所处SBMU编号";
CM_ SG_ 2332683937 M2P_CscPst_SysMaxTemp_HvOn17 "系统所有高压在线的电柜的最大电芯温度所处CSC编号";
CM_ SG_ 2332683937 M2P_SbmuPst_SysMinTemp_HvOn17 "系统所有高压在线的电柜的最小电芯温度所处SBMU编号";
CM_ SG_ 2332683937 M2P_CscPst_SysMinTemp_HvOn17 "系统所有高压在线的电柜的最小电芯温度所处CSC编号";
CM_ SG_ 2332683938 M2P_SysMaxTemp_HvOn18 "系统所有高压在线的电柜的最大电芯温度";
CM_ SG_ 2332683938 M2P_SysMinTemp_HvOn18 "系统所有高压在线的电柜的最小电芯温度";
CM_ SG_ 2332683938 M2P_SysAvgTemp_HvOn18 "系统所有高压在线的电柜的平均电芯温度";
CM_ SG_ 2332683938 M2P_SbmuPst_SysMaxTemp_HvOn18 "系统所有高压在线的电柜的最大电芯温度所处SBMU编号";
CM_ SG_ 2332683938 M2P_CscPst_SysMaxTemp_HvOn18 "系统所有高压在线的电柜的最大电芯温度所处CSC编号";
CM_ SG_ 2332683938 M2P_SbmuPst_SysMinTemp_HvOn18 "系统所有高压在线的电柜的最小电芯温度所处SBMU编号";
CM_ SG_ 2332683938 M2P_CscPst_SysMinTemp_HvOn18 "系统所有高压在线的电柜的最小电芯温度所处CSC编号";
CM_ SG_ 2332683939 M2P_SysMaxTemp_HvOn19 "系统所有高压在线的电柜的最大电芯温度";
CM_ SG_ 2332683939 M2P_SysMinTemp_HvOn19 "系统所有高压在线的电柜的最小电芯温度";
CM_ SG_ 2332683939 M2P_SysAvgTemp_HvOn19 "系统所有高压在线的电柜的平均电芯温度";
CM_ SG_ 2332683939 M2P_SbmuPst_SysMaxTemp_HvOn19 "系统所有高压在线的电柜的最大电芯温度所处SBMU编号";
CM_ SG_ 2332683939 M2P_CscPst_SysMaxTemp_HvOn19 "系统所有高压在线的电柜的最大电芯温度所处CSC编号";
CM_ SG_ 2332683939 M2P_SbmuPst_SysMinTemp_HvOn19 "系统所有高压在线的电柜的最小电芯温度所处SBMU编号";
CM_ SG_ 2332683939 M2P_CscPst_SysMinTemp_HvOn19 "系统所有高压在线的电柜的最小电芯温度所处CSC编号";
CM_ SG_ 2332683940 M2P_SysMaxTemp_HvOn20 "系统所有高压在线的电柜的最大电芯温度";
CM_ SG_ 2332683940 M2P_SysMinTemp_HvOn20 "系统所有高压在线的电柜的最小电芯温度";
CM_ SG_ 2332683940 M2P_SysAvgTemp_HvOn20 "系统所有高压在线的电柜的平均电芯温度";
CM_ SG_ 2332683940 M2P_SbmuPst_SysMaxTemp_HvOn20 "系统所有高压在线的电柜的最大电芯温度所处SBMU编号";
CM_ SG_ 2332683940 M2P_CscPst_SysMaxTemp_HvOn20 "系统所有高压在线的电柜的最大电芯温度所处CSC编号";
CM_ SG_ 2332683940 M2P_SbmuPst_SysMinTemp_HvOn20 "系统所有高压在线的电柜的最小电芯温度所处SBMU编号";
CM_ SG_ 2332683940 M2P_CscPst_SysMinTemp_HvOn20 "系统所有高压在线的电柜的最小电芯温度所处CSC编号";
CM_ SG_ 2332683941 M2P_SysMaxTemp_HvOn21 "系统所有高压在线的电柜的最大电芯温度";
CM_ SG_ 2332683941 M2P_SysMinTemp_HvOn21 "系统所有高压在线的电柜的最小电芯温度";
CM_ SG_ 2332683941 M2P_SysAvgTemp_HvOn21 "系统所有高压在线的电柜的平均电芯温度";
CM_ SG_ 2332683941 M2P_SbmuPst_SysMaxTemp_HvOn21 "系统所有高压在线的电柜的最大电芯温度所处SBMU编号";
CM_ SG_ 2332683941 M2P_CscPst_SysMaxTemp_HvOn21 "系统所有高压在线的电柜的最大电芯温度所处CSC编号";
CM_ SG_ 2332683941 M2P_SbmuPst_SysMinTemp_HvOn21 "系统所有高压在线的电柜的最小电芯温度所处SBMU编号";
CM_ SG_ 2332683941 M2P_CscPst_SysMinTemp_HvOn21 "系统所有高压在线的电柜的最小电芯温度所处CSC编号";
CM_ SG_ 2332683942 M2P_SysMaxTemp_HvOn22 "系统所有高压在线的电柜的最大电芯温度";
CM_ SG_ 2332683942 M2P_SysMinTemp_HvOn22 "系统所有高压在线的电柜的最小电芯温度";
CM_ SG_ 2332683942 M2P_SysAvgTemp_HvOn22 "系统所有高压在线的电柜的平均电芯温度";
CM_ SG_ 2332683942 M2P_SbmuPst_SysMaxTemp_HvOn22 "系统所有高压在线的电柜的最大电芯温度所处SBMU编号";
CM_ SG_ 2332683942 M2P_CscPst_SysMaxTemp_HvOn22 "系统所有高压在线的电柜的最大电芯温度所处CSC编号";
CM_ SG_ 2332683942 M2P_SbmuPst_SysMinTemp_HvOn22 "系统所有高压在线的电柜的最小电芯温度所处SBMU编号";
CM_ SG_ 2332683942 M2P_CscPst_SysMinTemp_HvOn22 "系统所有高压在线的电柜的最小电芯温度所处CSC编号";
CM_ SG_ 2332683943 M2P_SysMaxTemp_HvOn23 "系统所有高压在线的电柜的最大电芯温度";
CM_ SG_ 2332683943 M2P_SysMinTemp_HvOn23 "系统所有高压在线的电柜的最小电芯温度";
CM_ SG_ 2332683943 M2P_SysAvgTemp_HvOn23 "系统所有高压在线的电柜的平均电芯温度";
CM_ SG_ 2332683943 M2P_SbmuPst_SysMaxTemp_HvOn23 "系统所有高压在线的电柜的最大电芯温度所处SBMU编号";
CM_ SG_ 2332683943 M2P_CscPst_SysMaxTemp_HvOn23 "系统所有高压在线的电柜的最大电芯温度所处CSC编号";
CM_ SG_ 2332683943 M2P_SbmuPst_SysMinTemp_HvOn23 "系统所有高压在线的电柜的最小电芯温度所处SBMU编号";
CM_ SG_ 2332683943 M2P_CscPst_SysMinTemp_HvOn23 "系统所有高压在线的电柜的最小电芯温度所处CSC编号";
CM_ SG_ 2332683944 M2P_SysMaxTemp_HvOn24 "系统所有高压在线的电柜的最大电芯温度";
CM_ SG_ 2332683944 M2P_SysMinTemp_HvOn24 "系统所有高压在线的电柜的最小电芯温度";
CM_ SG_ 2332683944 M2P_SysAvgTemp_HvOn24 "系统所有高压在线的电柜的平均电芯温度";
CM_ SG_ 2332683944 M2P_SbmuPst_SysMaxTemp_HvOn24 "系统所有高压在线的电柜的最大电芯温度所处SBMU编号";
CM_ SG_ 2332683944 M2P_CscPst_SysMaxTemp_HvOn24 "系统所有高压在线的电柜的最大电芯温度所处CSC编号";
CM_ SG_ 2332683944 M2P_SbmuPst_SysMinTemp_HvOn24 "系统所有高压在线的电柜的最小电芯温度所处SBMU编号";
CM_ SG_ 2332683944 M2P_CscPst_SysMinTemp_HvOn24 "系统所有高压在线的电柜的最小电芯温度所处CSC编号";
CM_ SG_ 2332683945 M2P_SysMaxTemp_HvOn25 "系统所有高压在线的电柜的最大电芯温度";
CM_ SG_ 2332683945 M2P_SysMinTemp_HvOn25 "系统所有高压在线的电柜的最小电芯温度";
CM_ SG_ 2332683945 M2P_SysAvgTemp_HvOn25 "系统所有高压在线的电柜的平均电芯温度";
CM_ SG_ 2332683945 M2P_SbmuPst_SysMaxTemp_HvOn25 "系统所有高压在线的电柜的最大电芯温度所处SBMU编号";
CM_ SG_ 2332683945 M2P_CscPst_SysMaxTemp_HvOn25 "系统所有高压在线的电柜的最大电芯温度所处CSC编号";
CM_ SG_ 2332683945 M2P_SbmuPst_SysMinTemp_HvOn25 "系统所有高压在线的电柜的最小电芯温度所处SBMU编号";
CM_ SG_ 2332683945 M2P_CscPst_SysMinTemp_HvOn25 "系统所有高压在线的电柜的最小电芯温度所处CSC编号";
CM_ SG_ 2332683946 M2P_SysMaxTemp_HvOn26 "系统所有高压在线的电柜的最大电芯温度";
CM_ SG_ 2332683946 M2P_SysMinTemp_HvOn26 "系统所有高压在线的电柜的最小电芯温度";
CM_ SG_ 2332683946 M2P_SysAvgTemp_HvOn26 "系统所有高压在线的电柜的平均电芯温度";
CM_ SG_ 2332683946 M2P_SbmuPst_SysMaxTemp_HvOn26 "系统所有高压在线的电柜的最大电芯温度所处SBMU编号";
CM_ SG_ 2332683946 M2P_CscPst_SysMaxTemp_HvOn26 "系统所有高压在线的电柜的最大电芯温度所处CSC编号";
CM_ SG_ 2332683946 M2P_SbmuPst_SysMinTemp_HvOn26 "系统所有高压在线的电柜的最小电芯温度所处SBMU编号";
CM_ SG_ 2332683946 M2P_CscPst_SysMinTemp_HvOn26 "系统所有高压在线的电柜的最小电芯温度所处CSC编号";
CM_ SG_ 2332683947 M2P_SysMaxTemp_HvOn27 "系统所有高压在线的电柜的最大电芯温度";
CM_ SG_ 2332683947 M2P_SysMinTemp_HvOn27 "系统所有高压在线的电柜的最小电芯温度";
CM_ SG_ 2332683947 M2P_SysAvgTemp_HvOn27 "系统所有高压在线的电柜的平均电芯温度";
CM_ SG_ 2332683947 M2P_SbmuPst_SysMaxTemp_HvOn27 "系统所有高压在线的电柜的最大电芯温度所处SBMU编号";
CM_ SG_ 2332683947 M2P_CscPst_SysMaxTemp_HvOn27 "系统所有高压在线的电柜的最大电芯温度所处CSC编号";
CM_ SG_ 2332683947 M2P_SbmuPst_SysMinTemp_HvOn27 "系统所有高压在线的电柜的最小电芯温度所处SBMU编号";
CM_ SG_ 2332683947 M2P_CscPst_SysMinTemp_HvOn27 "系统所有高压在线的电柜的最小电芯温度所处CSC编号";
CM_ SG_ 2332683948 M2P_SysMaxTemp_HvOn28 "系统所有高压在线的电柜的最大电芯温度";
CM_ SG_ 2332683948 M2P_SysMinTemp_HvOn28 "系统所有高压在线的电柜的最小电芯温度";
CM_ SG_ 2332683948 M2P_SysAvgTemp_HvOn28 "系统所有高压在线的电柜的平均电芯温度";
CM_ SG_ 2332683948 M2P_SbmuPst_SysMaxTemp_HvOn28 "系统所有高压在线的电柜的最大电芯温度所处SBMU编号";
CM_ SG_ 2332683948 M2P_CscPst_SysMaxTemp_HvOn28 "系统所有高压在线的电柜的最大电芯温度所处CSC编号";
CM_ SG_ 2332683948 M2P_SbmuPst_SysMinTemp_HvOn28 "系统所有高压在线的电柜的最小电芯温度所处SBMU编号";
CM_ SG_ 2332683948 M2P_CscPst_SysMinTemp_HvOn28 "系统所有高压在线的电柜的最小电芯温度所处CSC编号";
VAL_ 2165465583 L2S_CMD1_CellHeatModeRequ1 0 "退出自加热模式" 1 "进入自加热模式" ;
VAL_ 2165465583 L2S_CMD1_CellHeatModeRequ2 0 "退出自加热模式" 1 "进入自加热模式" ;
VAL_ 2165465583 L2S_CMD1_CellHeatModeRequ3 0 "退出自加热模式" 1 "进入自加热模式" ;
VAL_ 2400644673 CSC_Tpole_No_01 1 "CSC 1" 2 "CSC 2" 3 "CSC 3" 4 "CSC 4" 5 "CSC 5" 6 "CSC 6" ;
VAL_ 2400644673 CSC_Tpole_01_01 255 "Invalid" ;
VAL_ 2400644673 CSC_Tpole_02_01 255 "Invalid" ;
VAL_ 2400644673 CSC_Tpole_03_01 255 "Invalid" ;
VAL_ 2400644673 CSC_Tpole_04_01 255 "Invalid" ;
VAL_ 2400644673 CSC_Tpole_05_01 255 "Invalid" ;
VAL_ 2400644673 CSC_Tpole_06_01 255 "Invalid" ;
VAL_ 2400644674 CSC_Tpole_No_02 1 "CSC 1" 2 "CSC 2" 3 "CSC 3" 4 "CSC 4" 5 "CSC 5" 6 "CSC 6" ;
VAL_ 2400644674 CSC_Tpole_01_02 255 "Invalid" ;
VAL_ 2400644674 CSC_Tpole_02_02 255 "Invalid" ;
VAL_ 2400644674 CSC_Tpole_03_02 255 "Invalid" ;
VAL_ 2400644674 CSC_Tpole_04_02 255 "Invalid" ;
VAL_ 2400644674 CSC_Tpole_05_02 255 "Invalid" ;
VAL_ 2400644674 CSC_Tpole_06_02 255 "Invalid" ;
VAL_ 2400644675 CSC_Tpole_No_03 1 "CSC 1" 2 "CSC 2" 3 "CSC 3" 4 "CSC 4" 5 "CSC 5" 6 "CSC 6" ;
VAL_ 2400644675 CSC_Tpole_01_03 255 "Invalid" ;
VAL_ 2400644675 CSC_Tpole_02_03 255 "Invalid" ;
VAL_ 2400644675 CSC_Tpole_03_03 255 "Invalid" ;
VAL_ 2400644675 CSC_Tpole_04_03 255 "Invalid" ;
VAL_ 2400644675 CSC_Tpole_05_03 255 "Invalid" ;
VAL_ 2400644675 CSC_Tpole_06_03 255 "Invalid" ;
VAL_ 2400644676 CSC_Tpole_No_04 1 "CSC 1" 2 "CSC 2" 3 "CSC 3" 4 "CSC 4" 5 "CSC 5" 6 "CSC 6" ;
VAL_ 2400644676 CSC_Tpole_01_04 255 "Invalid" ;
VAL_ 2400644676 CSC_Tpole_02_04 255 "Invalid" ;
VAL_ 2400644676 CSC_Tpole_03_04 255 "Invalid" ;
VAL_ 2400644676 CSC_Tpole_04_04 255 "Invalid" ;
VAL_ 2400644676 CSC_Tpole_05_04 255 "Invalid" ;
VAL_ 2400644676 CSC_Tpole_06_04 255 "Invalid" ;
VAL_ 2400644677 CSC_Tpole_No_05 1 "CSC 1" 2 "CSC 2" 3 "CSC 3" 4 "CSC 4" 5 "CSC 5" 6 "CSC 6" ;
VAL_ 2400644677 CSC_Tpole_01_05 255 "Invalid" ;
VAL_ 2400644677 CSC_Tpole_02_05 255 "Invalid" ;
VAL_ 2400644677 CSC_Tpole_03_05 255 "Invalid" ;
VAL_ 2400644677 CSC_Tpole_04_05 255 "Invalid" ;
VAL_ 2400644677 CSC_Tpole_05_05 255 "Invalid" ;
VAL_ 2400644677 CSC_Tpole_06_05 255 "Invalid" ;
VAL_ 2400644678 CSC_Tpole_No_06 1 "CSC 1" 2 "CSC 2" 3 "CSC 3" 4 "CSC 4" 5 "CSC 5" 6 "CSC 6" ;
VAL_ 2400644678 CSC_Tpole_01_06 255 "Invalid" ;
VAL_ 2400644678 CSC_Tpole_02_06 255 "Invalid" ;
VAL_ 2400644678 CSC_Tpole_03_06 255 "Invalid" ;
VAL_ 2400644678 CSC_Tpole_04_06 255 "Invalid" ;
VAL_ 2400644678 CSC_Tpole_05_06 255 "Invalid" ;
VAL_ 2400644678 CSC_Tpole_06_06 255 "Invalid" ;
VAL_ 2400644679 CSC_Tpole_No_07 1 "CSC 1" 2 "CSC 2" 3 "CSC 3" 4 "CSC 4" 5 "CSC 5" 6 "CSC 6" ;
VAL_ 2400644679 CSC_Tpole_01_07 255 "Invalid" ;
VAL_ 2400644679 CSC_Tpole_02_07 255 "Invalid" ;
VAL_ 2400644679 CSC_Tpole_03_07 255 "Invalid" ;
VAL_ 2400644679 CSC_Tpole_04_07 255 "Invalid" ;
VAL_ 2400644679 CSC_Tpole_05_07 255 "Invalid" ;
VAL_ 2400644679 CSC_Tpole_06_07 255 "Invalid" ;
VAL_ 2400644680 CSC_Tpole_No_08 1 "CSC 1" 2 "CSC 2" 3 "CSC 3" 4 "CSC 4" 5 "CSC 5" 6 "CSC 6" ;
VAL_ 2400644680 CSC_Tpole_01_08 255 "Invalid" ;
VAL_ 2400644680 CSC_Tpole_02_08 255 "Invalid" ;
VAL_ 2400644680 CSC_Tpole_03_08 255 "Invalid" ;
VAL_ 2400644680 CSC_Tpole_04_08 255 "Invalid" ;
VAL_ 2400644680 CSC_Tpole_05_08 255 "Invalid" ;
VAL_ 2400644680 CSC_Tpole_06_08 255 "Invalid" ;
VAL_ 2400644681 CSC_Tpole_No_09 1 "CSC 1" 2 "CSC 2" 3 "CSC 3" 4 "CSC 4" 5 "CSC 5" 6 "CSC 6" ;
VAL_ 2400644681 CSC_Tpole_01_09 255 "Invalid" ;
VAL_ 2400644681 CSC_Tpole_02_09 255 "Invalid" ;
VAL_ 2400644681 CSC_Tpole_03_09 255 "Invalid" ;
VAL_ 2400644681 CSC_Tpole_04_09 255 "Invalid" ;
VAL_ 2400644681 CSC_Tpole_05_09 255 "Invalid" ;
VAL_ 2400644681 CSC_Tpole_06_09 255 "Invalid" ;
VAL_ 2400644682 CSC_Tpole_No_10 1 "CSC 1" 2 "CSC 2" 3 "CSC 3" 4 "CSC 4" 5 "CSC 5" 6 "CSC 6" ;
VAL_ 2400644682 CSC_Tpole_01_10 255 "Invalid" ;
VAL_ 2400644682 CSC_Tpole_02_10 255 "Invalid" ;
VAL_ 2400644682 CSC_Tpole_03_10 255 "Invalid" ;
VAL_ 2400644682 CSC_Tpole_04_10 255 "Invalid" ;
VAL_ 2400644682 CSC_Tpole_05_10 255 "Invalid" ;
VAL_ 2400644682 CSC_Tpole_06_10 255 "Invalid" ;
VAL_ 2400644683 CSC_Tpole_No_11 1 "CSC 1" 2 "CSC 2" 3 "CSC 3" 4 "CSC 4" 5 "CSC 5" 6 "CSC 6" ;
VAL_ 2400644683 CSC_Tpole_01_11 255 "Invalid" ;
VAL_ 2400644683 CSC_Tpole_02_11 255 "Invalid" ;
VAL_ 2400644683 CSC_Tpole_03_11 255 "Invalid" ;
VAL_ 2400644683 CSC_Tpole_04_11 255 "Invalid" ;
VAL_ 2400644683 CSC_Tpole_05_11 255 "Invalid" ;
VAL_ 2400644683 CSC_Tpole_06_11 255 "Invalid" ;
VAL_ 2400644684 CSC_Tpole_No_12 1 "CSC 1" 2 "CSC 2" 3 "CSC 3" 4 "CSC 4" 5 "CSC 5" 6 "CSC 6" ;
VAL_ 2400644684 CSC_Tpole_01_12 255 "Invalid" ;
VAL_ 2400644684 CSC_Tpole_02_12 255 "Invalid" ;
VAL_ 2400644684 CSC_Tpole_03_12 255 "Invalid" ;
VAL_ 2400644684 CSC_Tpole_04_12 255 "Invalid" ;
VAL_ 2400644684 CSC_Tpole_05_12 255 "Invalid" ;
VAL_ 2400644684 CSC_Tpole_06_12 255 "Invalid" ;
VAL_ 2400644685 CSC_Tpole_No_13 1 "CSC 1" 2 "CSC 2" 3 "CSC 3" 4 "CSC 4" 5 "CSC 5" 6 "CSC 6" ;
VAL_ 2400644685 CSC_Tpole_01_13 255 "Invalid" ;
VAL_ 2400644685 CSC_Tpole_02_13 255 "Invalid" ;
VAL_ 2400644685 CSC_Tpole_03_13 255 "Invalid" ;
VAL_ 2400644685 CSC_Tpole_04_13 255 "Invalid" ;
VAL_ 2400644685 CSC_Tpole_05_13 255 "Invalid" ;
VAL_ 2400644685 CSC_Tpole_06_13 255 "Invalid" ;
VAL_ 2400644686 CSC_Tpole_No_14 1 "CSC 1" 2 "CSC 2" 3 "CSC 3" 4 "CSC 4" 5 "CSC 5" 6 "CSC 6" ;
VAL_ 2400644686 CSC_Tpole_01_14 255 "Invalid" ;
VAL_ 2400644686 CSC_Tpole_02_14 255 "Invalid" ;
VAL_ 2400644686 CSC_Tpole_03_14 255 "Invalid" ;
VAL_ 2400644686 CSC_Tpole_04_14 255 "Invalid" ;
VAL_ 2400644686 CSC_Tpole_05_14 255 "Invalid" ;
VAL_ 2400644686 CSC_Tpole_06_14 255 "Invalid" ;
VAL_ 2400644687 CSC_Tpole_No_15 1 "CSC 1" 2 "CSC 2" 3 "CSC 3" 4 "CSC 4" 5 "CSC 5" 6 "CSC 6" ;
VAL_ 2400644687 CSC_Tpole_01_15 255 "Invalid" ;
VAL_ 2400644687 CSC_Tpole_02_15 255 "Invalid" ;
VAL_ 2400644687 CSC_Tpole_03_15 255 "Invalid" ;
VAL_ 2400644687 CSC_Tpole_04_15 255 "Invalid" ;
VAL_ 2400644687 CSC_Tpole_05_15 255 "Invalid" ;
VAL_ 2400644687 CSC_Tpole_06_15 255 "Invalid" ;
VAL_ 2400644688 CSC_Tpole_No_16 1 "CSC 1" 2 "CSC 2" 3 "CSC 3" 4 "CSC 4" 5 "CSC 5" 6 "CSC 6" ;
VAL_ 2400644688 CSC_Tpole_01_16 255 "Invalid" ;
VAL_ 2400644688 CSC_Tpole_02_16 255 "Invalid" ;
VAL_ 2400644688 CSC_Tpole_03_16 255 "Invalid" ;
VAL_ 2400644688 CSC_Tpole_04_16 255 "Invalid" ;
VAL_ 2400644688 CSC_Tpole_05_16 255 "Invalid" ;
VAL_ 2400644688 CSC_Tpole_06_16 255 "Invalid" ;
VAL_ 2400644689 CSC_Tpole_No_17 1 "CSC 1" 2 "CSC 2" 3 "CSC 3" 4 "CSC 4" 5 "CSC 5" 6 "CSC 6" ;
VAL_ 2400644689 CSC_Tpole_01_17 255 "Invalid" ;
VAL_ 2400644689 CSC_Tpole_02_17 255 "Invalid" ;
VAL_ 2400644689 CSC_Tpole_03_17 255 "Invalid" ;
VAL_ 2400644689 CSC_Tpole_04_17 255 "Invalid" ;
VAL_ 2400644689 CSC_Tpole_05_17 255 "Invalid" ;
VAL_ 2400644689 CSC_Tpole_06_17 255 "Invalid" ;
VAL_ 2400644690 CSC_Tpole_No_18 1 "CSC 1" 2 "CSC 2" 3 "CSC 3" 4 "CSC 4" 5 "CSC 5" 6 "CSC 6" ;
VAL_ 2400644690 CSC_Tpole_01_18 255 "Invalid" ;
VAL_ 2400644690 CSC_Tpole_02_18 255 "Invalid" ;
VAL_ 2400644690 CSC_Tpole_03_18 255 "Invalid" ;
VAL_ 2400644690 CSC_Tpole_04_18 255 "Invalid" ;
VAL_ 2400644690 CSC_Tpole_05_18 255 "Invalid" ;
VAL_ 2400644690 CSC_Tpole_06_18 255 "Invalid" ;
VAL_ 2400644691 CSC_Tpole_No_19 1 "CSC 1" 2 "CSC 2" 3 "CSC 3" 4 "CSC 4" 5 "CSC 5" 6 "CSC 6" ;
VAL_ 2400644691 CSC_Tpole_01_19 255 "Invalid" ;
VAL_ 2400644691 CSC_Tpole_02_19 255 "Invalid" ;
VAL_ 2400644691 CSC_Tpole_03_19 255 "Invalid" ;
VAL_ 2400644691 CSC_Tpole_04_19 255 "Invalid" ;
VAL_ 2400644691 CSC_Tpole_05_19 255 "Invalid" ;
VAL_ 2400644691 CSC_Tpole_06_19 255 "Invalid" ;
VAL_ 2400644692 CSC_Tpole_No_20 1 "CSC 1" 2 "CSC 2" 3 "CSC 3" 4 "CSC 4" 5 "CSC 5" 6 "CSC 6" ;
VAL_ 2400644692 CSC_Tpole_01_20 255 "Invalid" ;
VAL_ 2400644692 CSC_Tpole_02_20 255 "Invalid" ;
VAL_ 2400644692 CSC_Tpole_03_20 255 "Invalid" ;
VAL_ 2400644692 CSC_Tpole_04_20 255 "Invalid" ;
VAL_ 2400644692 CSC_Tpole_05_20 255 "Invalid" ;
VAL_ 2400644692 CSC_Tpole_06_20 255 "Invalid" ;
VAL_ 2400644693 CSC_Tpole_No_21 1 "CSC 1" 2 "CSC 2" 3 "CSC 3" 4 "CSC 4" 5 "CSC 5" 6 "CSC 6" ;
VAL_ 2400644693 CSC_Tpole_01_21 255 "Invalid" ;
VAL_ 2400644693 CSC_Tpole_02_21 255 "Invalid" ;
VAL_ 2400644693 CSC_Tpole_03_21 255 "Invalid" ;
VAL_ 2400644693 CSC_Tpole_04_21 255 "Invalid" ;
VAL_ 2400644693 CSC_Tpole_05_21 255 "Invalid" ;
VAL_ 2400644693 CSC_Tpole_06_21 255 "Invalid" ;
VAL_ 2400644694 CSC_Tpole_No_22 1 "CSC 1" 2 "CSC 2" 3 "CSC 3" 4 "CSC 4" 5 "CSC 5" 6 "CSC 6" ;
VAL_ 2400644694 CSC_Tpole_01_22 255 "Invalid" ;
VAL_ 2400644694 CSC_Tpole_02_22 255 "Invalid" ;
VAL_ 2400644694 CSC_Tpole_03_22 255 "Invalid" ;
VAL_ 2400644694 CSC_Tpole_04_22 255 "Invalid" ;
VAL_ 2400644694 CSC_Tpole_05_22 255 "Invalid" ;
VAL_ 2400644694 CSC_Tpole_06_22 255 "Invalid" ;
VAL_ 2400644695 CSC_Tpole_No_23 1 "CSC 1" 2 "CSC 2" 3 "CSC 3" 4 "CSC 4" 5 "CSC 5" 6 "CSC 6" ;
VAL_ 2400644695 CSC_Tpole_01_23 255 "Invalid" ;
VAL_ 2400644695 CSC_Tpole_02_23 255 "Invalid" ;
VAL_ 2400644695 CSC_Tpole_03_23 255 "Invalid" ;
VAL_ 2400644695 CSC_Tpole_04_23 255 "Invalid" ;
VAL_ 2400644695 CSC_Tpole_05_23 255 "Invalid" ;
VAL_ 2400644695 CSC_Tpole_06_23 255 "Invalid" ;
VAL_ 2400644696 CSC_Tpole_No_24 1 "CSC 1" 2 "CSC 2" 3 "CSC 3" 4 "CSC 4" 5 "CSC 5" 6 "CSC 6" ;
VAL_ 2400644696 CSC_Tpole_01_24 255 "Invalid" ;
VAL_ 2400644696 CSC_Tpole_02_24 255 "Invalid" ;
VAL_ 2400644696 CSC_Tpole_03_24 255 "Invalid" ;
VAL_ 2400644696 CSC_Tpole_04_24 255 "Invalid" ;
VAL_ 2400644696 CSC_Tpole_05_24 255 "Invalid" ;
VAL_ 2400644696 CSC_Tpole_06_24 255 "Invalid" ;
VAL_ 2400644697 CSC_Tpole_No_25 1 "CSC 1" 2 "CSC 2" 3 "CSC 3" 4 "CSC 4" 5 "CSC 5" 6 "CSC 6" ;
VAL_ 2400644697 CSC_Tpole_01_25 255 "Invalid" ;
VAL_ 2400644697 CSC_Tpole_02_25 255 "Invalid" ;
VAL_ 2400644697 CSC_Tpole_03_25 255 "Invalid" ;
VAL_ 2400644697 CSC_Tpole_04_25 255 "Invalid" ;
VAL_ 2400644697 CSC_Tpole_05_25 255 "Invalid" ;
VAL_ 2400644697 CSC_Tpole_06_25 255 "Invalid" ;
VAL_ 2400644698 CSC_Tpole_No_26 1 "CSC 1" 2 "CSC 2" 3 "CSC 3" 4 "CSC 4" 5 "CSC 5" 6 "CSC 6" ;
VAL_ 2400644698 CSC_Tpole_01_26 255 "Invalid" ;
VAL_ 2400644698 CSC_Tpole_02_26 255 "Invalid" ;
VAL_ 2400644698 CSC_Tpole_03_26 255 "Invalid" ;
VAL_ 2400644698 CSC_Tpole_04_26 255 "Invalid" ;
VAL_ 2400644698 CSC_Tpole_05_26 255 "Invalid" ;
VAL_ 2400644698 CSC_Tpole_06_26 255 "Invalid" ;
VAL_ 2400644699 CSC_Tpole_No_27 1 "CSC 1" 2 "CSC 2" 3 "CSC 3" 4 "CSC 4" 5 "CSC 5" 6 "CSC 6" ;
VAL_ 2400644699 CSC_Tpole_01_27 255 "Invalid" ;
VAL_ 2400644699 CSC_Tpole_02_27 255 "Invalid" ;
VAL_ 2400644699 CSC_Tpole_03_27 255 "Invalid" ;
VAL_ 2400644699 CSC_Tpole_04_27 255 "Invalid" ;
VAL_ 2400644699 CSC_Tpole_05_27 255 "Invalid" ;
VAL_ 2400644699 CSC_Tpole_06_27 255 "Invalid" ;
VAL_ 2400644700 CSC_Tpole_No_28 1 "CSC 1" 2 "CSC 2" 3 "CSC 3" 4 "CSC 4" 5 "CSC 5" 6 "CSC 6" ;
VAL_ 2400644700 CSC_Tpole_01_28 255 "Invalid" ;
VAL_ 2400644700 CSC_Tpole_02_28 255 "Invalid" ;
VAL_ 2400644700 CSC_Tpole_03_28 255 "Invalid" ;
VAL_ 2400644700 CSC_Tpole_04_28 255 "Invalid" ;
VAL_ 2400644700 CSC_Tpole_05_28 255 "Invalid" ;
VAL_ 2400644700 CSC_Tpole_06_28 255 "Invalid" ;
VAL_ 2400644701 CSC_Tpole_No_29 1 "CSC 1" 2 "CSC 2" 3 "CSC 3" 4 "CSC 4" 5 "CSC 5" 6 "CSC 6" ;
VAL_ 2400644701 CSC_Tpole_01_29 255 "Invalid" ;
VAL_ 2400644701 CSC_Tpole_02_29 255 "Invalid" ;
VAL_ 2400644701 CSC_Tpole_03_29 255 "Invalid" ;
VAL_ 2400644701 CSC_Tpole_04_29 255 "Invalid" ;
VAL_ 2400644701 CSC_Tpole_05_29 255 "Invalid" ;
VAL_ 2400644701 CSC_Tpole_06_29 255 "Invalid" ;
VAL_ 2400644702 CSC_Tpole_No_30 1 "CSC 1" 2 "CSC 2" 3 "CSC 3" 4 "CSC 4" 5 "CSC 5" 6 "CSC 6" ;
VAL_ 2400644702 CSC_Tpole_01_30 255 "Invalid" ;
VAL_ 2400644702 CSC_Tpole_02_30 255 "Invalid" ;
VAL_ 2400644702 CSC_Tpole_03_30 255 "Invalid" ;
VAL_ 2400644702 CSC_Tpole_04_30 255 "Invalid" ;
VAL_ 2400644702 CSC_Tpole_05_30 255 "Invalid" ;
VAL_ 2400644702 CSC_Tpole_06_30 255 "Invalid" ;
VAL_ 2400644703 CSC_Tpole_No_31 1 "CSC 1" 2 "CSC 2" 3 "CSC 3" 4 "CSC 4" 5 "CSC 5" 6 "CSC 6" ;
VAL_ 2400644703 CSC_Tpole_01_31 255 "Invalid" ;
VAL_ 2400644703 CSC_Tpole_02_31 255 "Invalid" ;
VAL_ 2400644703 CSC_Tpole_03_31 255 "Invalid" ;
VAL_ 2400644703 CSC_Tpole_04_31 255 "Invalid" ;
VAL_ 2400644703 CSC_Tpole_05_31 255 "Invalid" ;
VAL_ 2400644703 CSC_Tpole_06_31 255 "Invalid" ;
VAL_ 2400644704 CSC_Tpole_No_32 1 "CSC 1" 2 "CSC 2" 3 "CSC 3" 4 "CSC 4" 5 "CSC 5" 6 "CSC 6" ;
VAL_ 2400644704 CSC_Tpole_01_32 255 "Invalid" ;
VAL_ 2400644704 CSC_Tpole_02_32 255 "Invalid" ;
VAL_ 2400644704 CSC_Tpole_03_32 255 "Invalid" ;
VAL_ 2400644704 CSC_Tpole_04_32 255 "Invalid" ;
VAL_ 2400644704 CSC_Tpole_05_32 255 "Invalid" ;
VAL_ 2400644704 CSC_Tpole_06_32 255 "Invalid" ;
VAL_ 2400644705 CSC_Tpole_No_33 1 "CSC 1" 2 "CSC 2" 3 "CSC 3" 4 "CSC 4" 5 "CSC 5" 6 "CSC 6" ;
VAL_ 2400644705 CSC_Tpole_01_33 255 "Invalid" ;
VAL_ 2400644705 CSC_Tpole_02_33 255 "Invalid" ;
VAL_ 2400644705 CSC_Tpole_03_33 255 "Invalid" ;
VAL_ 2400644705 CSC_Tpole_04_33 255 "Invalid" ;
VAL_ 2400644705 CSC_Tpole_05_33 255 "Invalid" ;
VAL_ 2400644705 CSC_Tpole_06_33 255 "Invalid" ;
VAL_ 2400644706 CSC_Tpole_No_34 1 "CSC 1" 2 "CSC 2" 3 "CSC 3" 4 "CSC 4" 5 "CSC 5" 6 "CSC 6" ;
VAL_ 2400644706 CSC_Tpole_01_34 255 "Invalid" ;
VAL_ 2400644706 CSC_Tpole_02_34 255 "Invalid" ;
VAL_ 2400644706 CSC_Tpole_03_34 255 "Invalid" ;
VAL_ 2400644706 CSC_Tpole_04_34 255 "Invalid" ;
VAL_ 2400644706 CSC_Tpole_05_34 255 "Invalid" ;
VAL_ 2400644706 CSC_Tpole_06_34 255 "Invalid" ;
VAL_ 2400644707 CSC_Tpole_No_35 1 "CSC 1" 2 "CSC 2" 3 "CSC 3" 4 "CSC 4" 5 "CSC 5" 6 "CSC 6" ;
VAL_ 2400644707 CSC_Tpole_01_35 255 "Invalid" ;
VAL_ 2400644707 CSC_Tpole_02_35 255 "Invalid" ;
VAL_ 2400644707 CSC_Tpole_03_35 255 "Invalid" ;
VAL_ 2400644707 CSC_Tpole_04_35 255 "Invalid" ;
VAL_ 2400644707 CSC_Tpole_05_35 255 "Invalid" ;
VAL_ 2400644707 CSC_Tpole_06_35 255 "Invalid" ;
VAL_ 2400644708 CSC_Tpole_No_36 1 "CSC 1" 2 "CSC 2" 3 "CSC 3" 4 "CSC 4" 5 "CSC 5" 6 "CSC 6" ;
VAL_ 2400644708 CSC_Tpole_01_36 255 "Invalid" ;
VAL_ 2400644708 CSC_Tpole_02_36 255 "Invalid" ;
VAL_ 2400644708 CSC_Tpole_03_36 255 "Invalid" ;
VAL_ 2400644708 CSC_Tpole_04_36 255 "Invalid" ;
VAL_ 2400644708 CSC_Tpole_05_36 255 "Invalid" ;
VAL_ 2400644708 CSC_Tpole_06_36 255 "Invalid" ;
VAL_ 2400644709 CSC_Tpole_No_37 1 "CSC 1" 2 "CSC 2" 3 "CSC 3" 4 "CSC 4" 5 "CSC 5" 6 "CSC 6" ;
VAL_ 2400644709 CSC_Tpole_01_37 255 "Invalid" ;
VAL_ 2400644709 CSC_Tpole_02_37 255 "Invalid" ;
VAL_ 2400644709 CSC_Tpole_03_37 255 "Invalid" ;
VAL_ 2400644709 CSC_Tpole_04_37 255 "Invalid" ;
VAL_ 2400644709 CSC_Tpole_05_37 255 "Invalid" ;
VAL_ 2400644709 CSC_Tpole_06_37 255 "Invalid" ;
VAL_ 2400644710 CSC_Tpole_No_38 1 "CSC 1" 2 "CSC 2" 3 "CSC 3" 4 "CSC 4" 5 "CSC 5" 6 "CSC 6" ;
VAL_ 2400644710 CSC_Tpole_01_38 255 "Invalid" ;
VAL_ 2400644710 CSC_Tpole_02_38 255 "Invalid" ;
VAL_ 2400644710 CSC_Tpole_03_38 255 "Invalid" ;
VAL_ 2400644710 CSC_Tpole_04_38 255 "Invalid" ;
VAL_ 2400644710 CSC_Tpole_05_38 255 "Invalid" ;
VAL_ 2400644710 CSC_Tpole_06_38 255 "Invalid" ;
VAL_ 2400644711 CSC_Tpole_No_39 1 "CSC 1" 2 "CSC 2" 3 "CSC 3" 4 "CSC 4" 5 "CSC 5" 6 "CSC 6" ;
VAL_ 2400644711 CSC_Tpole_01_39 255 "Invalid" ;
VAL_ 2400644711 CSC_Tpole_02_39 255 "Invalid" ;
VAL_ 2400644711 CSC_Tpole_03_39 255 "Invalid" ;
VAL_ 2400644711 CSC_Tpole_04_39 255 "Invalid" ;
VAL_ 2400644711 CSC_Tpole_05_39 255 "Invalid" ;
VAL_ 2400644711 CSC_Tpole_06_39 255 "Invalid" ;
VAL_ 2400644712 CSC_Tpole_No_40 1 "CSC 1" 2 "CSC 2" 3 "CSC 3" 4 "CSC 4" 5 "CSC 5" 6 "CSC 6" ;
VAL_ 2400644712 CSC_Tpole_01_40 255 "Invalid" ;
VAL_ 2400644712 CSC_Tpole_02_40 255 "Invalid" ;
VAL_ 2400644712 CSC_Tpole_03_40 255 "Invalid" ;
VAL_ 2400644712 CSC_Tpole_04_40 255 "Invalid" ;
VAL_ 2400644712 CSC_Tpole_05_40 255 "Invalid" ;
VAL_ 2400644712 CSC_Tpole_06_40 255 "Invalid" ;
VAL_ 2400644713 CSC_Tpole_No_41 1 "CSC 1" 2 "CSC 2" 3 "CSC 3" 4 "CSC 4" 5 "CSC 5" 6 "CSC 6" ;
VAL_ 2400644713 CSC_Tpole_01_41 255 "Invalid" ;
VAL_ 2400644713 CSC_Tpole_02_41 255 "Invalid" ;
VAL_ 2400644713 CSC_Tpole_03_41 255 "Invalid" ;
VAL_ 2400644713 CSC_Tpole_04_41 255 "Invalid" ;
VAL_ 2400644713 CSC_Tpole_05_41 255 "Invalid" ;
VAL_ 2400644713 CSC_Tpole_06_41 255 "Invalid" ;
VAL_ 2400644714 CSC_Tpole_No_42 1 "CSC 1" 2 "CSC 2" 3 "CSC 3" 4 "CSC 4" 5 "CSC 5" 6 "CSC 6" ;
VAL_ 2400644714 CSC_Tpole_01_42 255 "Invalid" ;
VAL_ 2400644714 CSC_Tpole_02_42 255 "Invalid" ;
VAL_ 2400644714 CSC_Tpole_03_42 255 "Invalid" ;
VAL_ 2400644714 CSC_Tpole_04_42 255 "Invalid" ;
VAL_ 2400644714 CSC_Tpole_05_42 255 "Invalid" ;
VAL_ 2400644714 CSC_Tpole_06_42 255 "Invalid" ;
VAL_ 2400644715 CSC_Tpole_No_43 1 "CSC 1" 2 "CSC 2" 3 "CSC 3" 4 "CSC 4" 5 "CSC 5" 6 "CSC 6" ;
VAL_ 2400644715 CSC_Tpole_01_43 255 "Invalid" ;
VAL_ 2400644715 CSC_Tpole_02_43 255 "Invalid" ;
VAL_ 2400644715 CSC_Tpole_03_43 255 "Invalid" ;
VAL_ 2400644715 CSC_Tpole_04_43 255 "Invalid" ;
VAL_ 2400644715 CSC_Tpole_05_43 255 "Invalid" ;
VAL_ 2400644715 CSC_Tpole_06_43 255 "Invalid" ;
VAL_ 2400644716 CSC_Tpole_No_44 1 "CSC 1" 2 "CSC 2" 3 "CSC 3" 4 "CSC 4" 5 "CSC 5" 6 "CSC 6" ;
VAL_ 2400644716 CSC_Tpole_01_44 255 "Invalid" ;
VAL_ 2400644716 CSC_Tpole_02_44 255 "Invalid" ;
VAL_ 2400644716 CSC_Tpole_03_44 255 "Invalid" ;
VAL_ 2400644716 CSC_Tpole_04_44 255 "Invalid" ;
VAL_ 2400644716 CSC_Tpole_05_44 255 "Invalid" ;
VAL_ 2400644716 CSC_Tpole_06_44 255 "Invalid" ;
VAL_ 2400644717 CSC_Tpole_No_45 1 "CSC 1" 2 "CSC 2" 3 "CSC 3" 4 "CSC 4" 5 "CSC 5" 6 "CSC 6" ;
VAL_ 2400644717 CSC_Tpole_01_45 255 "Invalid" ;
VAL_ 2400644717 CSC_Tpole_02_45 255 "Invalid" ;
VAL_ 2400644717 CSC_Tpole_03_45 255 "Invalid" ;
VAL_ 2400644717 CSC_Tpole_04_45 255 "Invalid" ;
VAL_ 2400644717 CSC_Tpole_05_45 255 "Invalid" ;
VAL_ 2400644717 CSC_Tpole_06_45 255 "Invalid" ;
VAL_ 2400644718 CSC_Tpole_No_46 1 "CSC 1" 2 "CSC 2" 3 "CSC 3" 4 "CSC 4" 5 "CSC 5" 6 "CSC 6" ;
VAL_ 2400644718 CSC_Tpole_01_46 255 "Invalid" ;
VAL_ 2400644718 CSC_Tpole_02_46 255 "Invalid" ;
VAL_ 2400644718 CSC_Tpole_03_46 255 "Invalid" ;
VAL_ 2400644718 CSC_Tpole_04_46 255 "Invalid" ;
VAL_ 2400644718 CSC_Tpole_05_46 255 "Invalid" ;
VAL_ 2400644718 CSC_Tpole_06_46 255 "Invalid" ;
VAL_ 2400644719 CSC_Tpole_No_47 1 "CSC 1" 2 "CSC 2" 3 "CSC 3" 4 "CSC 4" 5 "CSC 5" 6 "CSC 6" ;
VAL_ 2400644719 CSC_Tpole_01_47 255 "Invalid" ;
VAL_ 2400644719 CSC_Tpole_02_47 255 "Invalid" ;
VAL_ 2400644719 CSC_Tpole_03_47 255 "Invalid" ;
VAL_ 2400644719 CSC_Tpole_04_47 255 "Invalid" ;
VAL_ 2400644719 CSC_Tpole_05_47 255 "Invalid" ;
VAL_ 2400644719 CSC_Tpole_06_47 255 "Invalid" ;
VAL_ 2400644720 CSC_Tpole_No_48 1 "CSC 1" 2 "CSC 2" 3 "CSC 3" 4 "CSC 4" 5 "CSC 5" 6 "CSC 6" ;
VAL_ 2400644720 CSC_Tpole_01_48 255 "Invalid" ;
VAL_ 2400644720 CSC_Tpole_02_48 255 "Invalid" ;
VAL_ 2400644720 CSC_Tpole_03_48 255 "Invalid" ;
VAL_ 2400644720 CSC_Tpole_04_48 255 "Invalid" ;
VAL_ 2400644720 CSC_Tpole_05_48 255 "Invalid" ;
VAL_ 2400644720 CSC_Tpole_06_48 255 "Invalid" ;
VAL_ 2400644721 CSC_Tpole_No_49 1 "CSC 1" 2 "CSC 2" 3 "CSC 3" 4 "CSC 4" 5 "CSC 5" 6 "CSC 6" ;
VAL_ 2400644721 CSC_Tpole_01_49 255 "Invalid" ;
VAL_ 2400644721 CSC_Tpole_02_49 255 "Invalid" ;
VAL_ 2400644721 CSC_Tpole_03_49 255 "Invalid" ;
VAL_ 2400644721 CSC_Tpole_04_49 255 "Invalid" ;
VAL_ 2400644721 CSC_Tpole_05_49 255 "Invalid" ;
VAL_ 2400644721 CSC_Tpole_06_49 255 "Invalid" ;
VAL_ 2400644722 CSC_Tpole_No_50 1 "CSC 1" 2 "CSC 2" 3 "CSC 3" 4 "CSC 4" 5 "CSC 5" 6 "CSC 6" ;
VAL_ 2400644722 CSC_Tpole_01_50 255 "Invalid" ;
VAL_ 2400644722 CSC_Tpole_02_50 255 "Invalid" ;
VAL_ 2400644722 CSC_Tpole_03_50 255 "Invalid" ;
VAL_ 2400644722 CSC_Tpole_04_50 255 "Invalid" ;
VAL_ 2400644722 CSC_Tpole_05_50 255 "Invalid" ;
VAL_ 2400644722 CSC_Tpole_06_50 255 "Invalid" ;
VAL_ 2400644723 CSC_Tpole_No_51 1 "CSC 1" 2 "CSC 2" 3 "CSC 3" 4 "CSC 4" 5 "CSC 5" 6 "CSC 6" ;
VAL_ 2400644723 CSC_Tpole_01_51 255 "Invalid" ;
VAL_ 2400644723 CSC_Tpole_02_51 255 "Invalid" ;
VAL_ 2400644723 CSC_Tpole_03_51 255 "Invalid" ;
VAL_ 2400644723 CSC_Tpole_04_51 255 "Invalid" ;
VAL_ 2400644723 CSC_Tpole_05_51 255 "Invalid" ;
VAL_ 2400644723 CSC_Tpole_06_51 255 "Invalid" ;
VAL_ 2400644724 CSC_Tpole_No_52 1 "CSC 1" 2 "CSC 2" 3 "CSC 3" 4 "CSC 4" 5 "CSC 5" 6 "CSC 6" ;
VAL_ 2400644724 CSC_Tpole_01_52 255 "Invalid" ;
VAL_ 2400644724 CSC_Tpole_02_52 255 "Invalid" ;
VAL_ 2400644724 CSC_Tpole_03_52 255 "Invalid" ;
VAL_ 2400644724 CSC_Tpole_04_52 255 "Invalid" ;
VAL_ 2400644724 CSC_Tpole_05_52 255 "Invalid" ;
VAL_ 2400644724 CSC_Tpole_06_52 255 "Invalid" ;
VAL_ 2400644725 CSC_Tpole_No_53 1 "CSC 1" 2 "CSC 2" 3 "CSC 3" 4 "CSC 4" 5 "CSC 5" 6 "CSC 6" ;
VAL_ 2400644725 CSC_Tpole_01_53 255 "Invalid" ;
VAL_ 2400644725 CSC_Tpole_02_53 255 "Invalid" ;
VAL_ 2400644725 CSC_Tpole_03_53 255 "Invalid" ;
VAL_ 2400644725 CSC_Tpole_04_53 255 "Invalid" ;
VAL_ 2400644725 CSC_Tpole_05_53 255 "Invalid" ;
VAL_ 2400644725 CSC_Tpole_06_53 255 "Invalid" ;
VAL_ 2400644726 CSC_Tpole_No_54 1 "CSC 1" 2 "CSC 2" 3 "CSC 3" 4 "CSC 4" 5 "CSC 5" 6 "CSC 6" ;
VAL_ 2400644726 CSC_Tpole_01_54 255 "Invalid" ;
VAL_ 2400644726 CSC_Tpole_02_54 255 "Invalid" ;
VAL_ 2400644726 CSC_Tpole_03_54 255 "Invalid" ;
VAL_ 2400644726 CSC_Tpole_04_54 255 "Invalid" ;
VAL_ 2400644726 CSC_Tpole_05_54 255 "Invalid" ;
VAL_ 2400644726 CSC_Tpole_06_54 255 "Invalid" ;
VAL_ 2400644727 CSC_Tpole_No_55 1 "CSC 1" 2 "CSC 2" 3 "CSC 3" 4 "CSC 4" 5 "CSC 5" 6 "CSC 6" ;
VAL_ 2400644727 CSC_Tpole_01_55 255 "Invalid" ;
VAL_ 2400644727 CSC_Tpole_02_55 255 "Invalid" ;
VAL_ 2400644727 CSC_Tpole_03_55 255 "Invalid" ;
VAL_ 2400644727 CSC_Tpole_04_55 255 "Invalid" ;
VAL_ 2400644727 CSC_Tpole_05_55 255 "Invalid" ;
VAL_ 2400644727 CSC_Tpole_06_55 255 "Invalid" ;
VAL_ 2400644728 CSC_Tpole_No_56 1 "CSC 1" 2 "CSC 2" 3 "CSC 3" 4 "CSC 4" 5 "CSC 5" 6 "CSC 6" ;
VAL_ 2400644728 CSC_Tpole_01_56 255 "Invalid" ;
VAL_ 2400644728 CSC_Tpole_02_56 255 "Invalid" ;
VAL_ 2400644728 CSC_Tpole_03_56 255 "Invalid" ;
VAL_ 2400644728 CSC_Tpole_04_56 255 "Invalid" ;
VAL_ 2400644728 CSC_Tpole_05_56 255 "Invalid" ;
VAL_ 2400644728 CSC_Tpole_06_56 255 "Invalid" ;
VAL_ 2400644729 CSC_Tpole_No_57 1 "CSC 1" 2 "CSC 2" 3 "CSC 3" 4 "CSC 4" 5 "CSC 5" 6 "CSC 6" ;
VAL_ 2400644729 CSC_Tpole_01_57 255 "Invalid" ;
VAL_ 2400644729 CSC_Tpole_02_57 255 "Invalid" ;
VAL_ 2400644729 CSC_Tpole_03_57 255 "Invalid" ;
VAL_ 2400644729 CSC_Tpole_04_57 255 "Invalid" ;
VAL_ 2400644729 CSC_Tpole_05_57 255 "Invalid" ;
VAL_ 2400644729 CSC_Tpole_06_57 255 "Invalid" ;
VAL_ 2400644730 CSC_Tpole_No_58 1 "CSC 1" 2 "CSC 2" 3 "CSC 3" 4 "CSC 4" 5 "CSC 5" 6 "CSC 6" ;
VAL_ 2400644730 CSC_Tpole_01_58 255 "Invalid" ;
VAL_ 2400644730 CSC_Tpole_02_58 255 "Invalid" ;
VAL_ 2400644730 CSC_Tpole_03_58 255 "Invalid" ;
VAL_ 2400644730 CSC_Tpole_04_58 255 "Invalid" ;
VAL_ 2400644730 CSC_Tpole_05_58 255 "Invalid" ;
VAL_ 2400644730 CSC_Tpole_06_58 255 "Invalid" ;
VAL_ 2400644731 CSC_Tpole_No_59 1 "CSC 1" 2 "CSC 2" 3 "CSC 3" 4 "CSC 4" 5 "CSC 5" 6 "CSC 6" ;
VAL_ 2400644731 CSC_Tpole_01_59 255 "Invalid" ;
VAL_ 2400644731 CSC_Tpole_02_59 255 "Invalid" ;
VAL_ 2400644731 CSC_Tpole_03_59 255 "Invalid" ;
VAL_ 2400644731 CSC_Tpole_04_59 255 "Invalid" ;
VAL_ 2400644731 CSC_Tpole_05_59 255 "Invalid" ;
VAL_ 2400644731 CSC_Tpole_06_59 255 "Invalid" ;
VAL_ 2400644732 CSC_Tpole_No_60 1 "CSC 1" 2 "CSC 2" 3 "CSC 3" 4 "CSC 4" 5 "CSC 5" 6 "CSC 6" ;
VAL_ 2400644732 CSC_Tpole_01_60 255 "Invalid" ;
VAL_ 2400644732 CSC_Tpole_02_60 255 "Invalid" ;
VAL_ 2400644732 CSC_Tpole_03_60 255 "Invalid" ;
VAL_ 2400644732 CSC_Tpole_04_60 255 "Invalid" ;
VAL_ 2400644732 CSC_Tpole_05_60 255 "Invalid" ;
VAL_ 2400644732 CSC_Tpole_06_60 255 "Invalid" ;
VAL_ 2400644733 CSC_Tpole_No_61 1 "CSC 1" 2 "CSC 2" 3 "CSC 3" 4 "CSC 4" 5 "CSC 5" 6 "CSC 6" ;
VAL_ 2400644733 CSC_Tpole_01_61 255 "Invalid" ;
VAL_ 2400644733 CSC_Tpole_02_61 255 "Invalid" ;
VAL_ 2400644733 CSC_Tpole_03_61 255 "Invalid" ;
VAL_ 2400644733 CSC_Tpole_04_61 255 "Invalid" ;
VAL_ 2400644733 CSC_Tpole_05_61 255 "Invalid" ;
VAL_ 2400644733 CSC_Tpole_06_61 255 "Invalid" ;
VAL_ 2400644734 CSC_Tpole_No_62 1 "CSC 1" 2 "CSC 2" 3 "CSC 3" 4 "CSC 4" 5 "CSC 5" 6 "CSC 6" ;
VAL_ 2400644734 CSC_Tpole_01_62 255 "Invalid" ;
VAL_ 2400644734 CSC_Tpole_02_62 255 "Invalid" ;
VAL_ 2400644734 CSC_Tpole_03_62 255 "Invalid" ;
VAL_ 2400644734 CSC_Tpole_04_62 255 "Invalid" ;
VAL_ 2400644734 CSC_Tpole_05_62 255 "Invalid" ;
VAL_ 2400644734 CSC_Tpole_06_62 255 "Invalid" ;
VAL_ 2400644735 CSC_Tpole_No_63 1 "CSC 1" 2 "CSC 2" 3 "CSC 3" 4 "CSC 4" 5 "CSC 5" 6 "CSC 6" ;
VAL_ 2400644735 CSC_Tpole_01_63 255 "Invalid" ;
VAL_ 2400644735 CSC_Tpole_02_63 255 "Invalid" ;
VAL_ 2400644735 CSC_Tpole_03_63 255 "Invalid" ;
VAL_ 2400644735 CSC_Tpole_04_63 255 "Invalid" ;
VAL_ 2400644735 CSC_Tpole_05_63 255 "Invalid" ;
VAL_ 2400644735 CSC_Tpole_06_63 255 "Invalid" ;
VERSION ""

NS_ :

BS_:

BU_: MBMU PC SBMU IMM ETH DCDC LEMS

BO_ 2332683949 M2P_SUMDATA9__29: 8 MBMU
 SG_ M2P_SysMaxTemp_HvOn29 : 0|8@1+ (1,-50) [0|205] "℃"  PC
 SG_ M2P_SysMinTemp_HvOn29 : 8|8@1+ (1,-50) [0|205] "℃"  PC
 SG_ M2P_SysAvgTemp_HvOn29 : 16|8@1+ (1,-50) [0|205] "℃"  PC
 SG_ M2P_SbmuPst_SysMaxTemp_HvOn29 : 24|8@1+ (1,0) [0|255] ""  PC
 SG_ M2P_CscPst_SysMaxTemp_HvOn29 : 32|8@1+ (1,0) [0|255] ""  PC
 SG_ M2P_SbmuPst_SysMinTemp_HvOn29 : 40|8@1+ (1,0) [0|255] ""  PC
 SG_ M2P_CscPst_SysMinTemp_HvOn29 : 48|8@1+ (1,0) [0|255] ""  PC

BO_ 2332683950 M2P_SUMDATA9__30: 8 MBMU
 SG_ M2P_SysMaxTemp_HvOn30 : 0|8@1+ (1,-50) [0|205] "℃"  PC
 SG_ M2P_SysMinTemp_HvOn30 : 8|8@1+ (1,-50) [0|205] "℃"  PC
 SG_ M2P_SysAvgTemp_HvOn30 : 16|8@1+ (1,-50) [0|205] "℃"  PC
 SG_ M2P_SbmuPst_SysMaxTemp_HvOn30 : 24|8@1+ (1,0) [0|255] ""  PC
 SG_ M2P_CscPst_SysMaxTemp_HvOn30 : 32|8@1+ (1,0) [0|255] ""  PC
 SG_ M2P_SbmuPst_SysMinTemp_HvOn30 : 40|8@1+ (1,0) [0|255] ""  PC
 SG_ M2P_CscPst_SysMinTemp_HvOn30 : 48|8@1+ (1,0) [0|255] ""  PC

BO_ 2332683951 M2P_SUMDATA9__31: 8 MBMU
 SG_ M2P_SysMaxTemp_HvOn31 : 0|8@1+ (1,-50) [0|205] "℃"  PC
 SG_ M2P_SysMinTemp_HvOn31 : 8|8@1+ (1,-50) [0|205] "℃"  PC
 SG_ M2P_SysAvgTemp_HvOn31 : 16|8@1+ (1,-50) [0|205] "℃"  PC
 SG_ M2P_SbmuPst_SysMaxTemp_HvOn31 : 24|8@1+ (1,0) [0|255] ""  PC
 SG_ M2P_CscPst_SysMaxTemp_HvOn31 : 32|8@1+ (1,0) [0|255] ""  PC
 SG_ M2P_SbmuPst_SysMinTemp_HvOn31 : 40|8@1+ (1,0) [0|255] ""  PC
 SG_ M2P_CscPst_SysMinTemp_HvOn31 : 48|8@1+ (1,0) [0|255] ""  PC

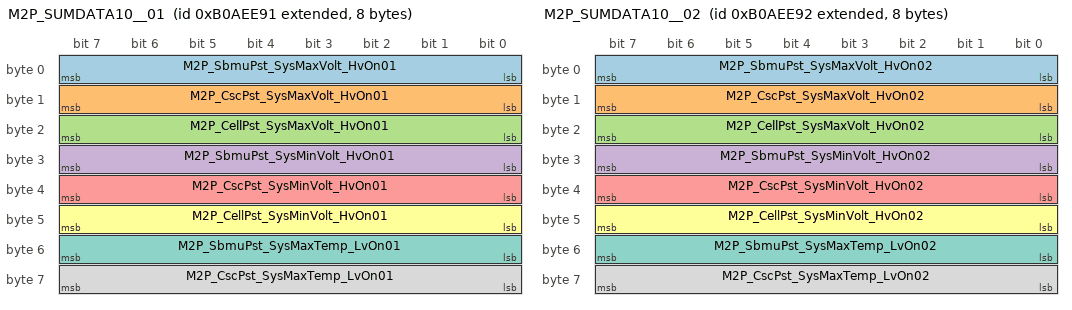
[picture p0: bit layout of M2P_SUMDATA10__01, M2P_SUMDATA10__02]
BO_ 2332749457 M2P_SUMDATA10__01: 8 MBMU
 SG_ M2P_SbmuPst_SysMaxVolt_HvOn01 : 0|8@1+ (1,0) [0|255] ""  PC
 SG_ M2P_CscPst_SysMaxVolt_HvOn01 : 8|8@1+ (1,0) [0|255] ""  PC
 SG_ M2P_CellPst_SysMaxVolt_HvOn01 : 16|8@1+ (1,0) [0|255] ""  PC
 SG_ M2P_SbmuPst_SysMinVolt_HvOn01 : 24|8@1+ (1,0) [0|255] ""  PC
 SG_ M2P_CscPst_SysMinVolt_HvOn01 : 32|8@1+ (1,0) [0|255] ""  PC
 SG_ M2P_CellPst_SysMinVolt_HvOn01 : 40|8@1+ (1,0) [0|255] ""  PC
 SG_ M2P_SbmuPst_SysMaxTemp_LvOn01 : 48|8@1+ (1,0) [0|255] ""  PC
 SG_ M2P_CscPst_SysMaxTemp_LvOn01 : 56|8@1+ (1,0) [0|255] ""  PC

BO_ 2332749458 M2P_SUMDATA10__02: 8 MBMU
 SG_ M2P_SbmuPst_SysMaxVolt_HvOn02 : 0|8@1+ (1,0) [0|255] ""  PC
 SG_ M2P_CscPst_SysMaxVolt_HvOn02 : 8|8@1+ (1,0) [0|255] ""  PC
 SG_ M2P_CellPst_SysMaxVolt_HvOn02 : 16|8@1+ (1,0) [0|255] ""  PC
 SG_ M2P_SbmuPst_SysMinVolt_HvOn02 : 24|8@1+ (1,0) [0|255] ""  PC
 SG_ M2P_CscPst_SysMinVolt_HvOn02 : 32|8@1+ (1,0) [0|255] ""  PC
 SG_ M2P_CellPst_SysMinVolt_HvOn02 : 40|8@1+ (1,0) [0|255] ""  PC
 SG_ M2P_SbmuPst_SysMaxTemp_LvOn02 : 48|8@1+ (1,0) [0|255] ""  PC
 SG_ M2P_CscPst_SysMaxTemp_LvOn02 : 56|8@1+ (1,0) [0|255] ""  PC

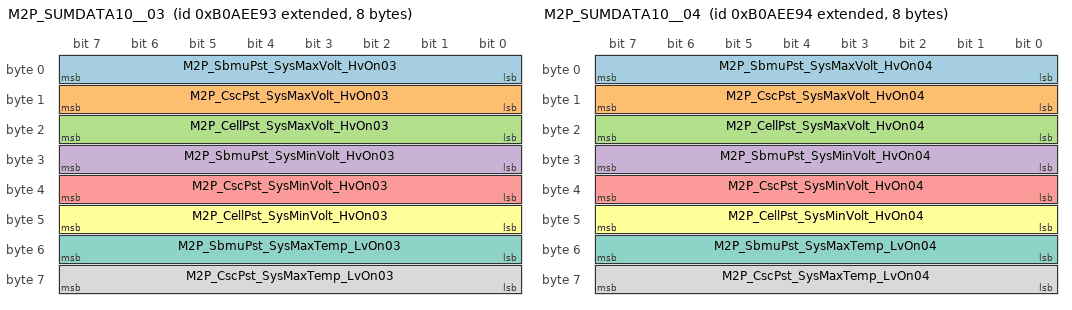
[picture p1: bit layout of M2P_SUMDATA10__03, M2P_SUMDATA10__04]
BO_ 2332749459 M2P_SUMDATA10__03: 8 MBMU
 SG_ M2P_SbmuPst_SysMaxVolt_HvOn03 : 0|8@1+ (1,0) [0|255] ""  PC
 SG_ M2P_CscPst_SysMaxVolt_HvOn03 : 8|8@1+ (1,0) [0|255] ""  PC
 SG_ M2P_CellPst_SysMaxVolt_HvOn03 : 16|8@1+ (1,0) [0|255] ""  PC
 SG_ M2P_SbmuPst_SysMinVolt_HvOn03 : 24|8@1+ (1,0) [0|255] ""  PC
 SG_ M2P_CscPst_SysMinVolt_HvOn03 : 32|8@1+ (1,0) [0|255] ""  PC
 SG_ M2P_CellPst_SysMinVolt_HvOn03 : 40|8@1+ (1,0) [0|255] ""  PC
 SG_ M2P_SbmuPst_SysMaxTemp_LvOn03 : 48|8@1+ (1,0) [0|255] ""  PC
 SG_ M2P_CscPst_SysMaxTemp_LvOn03 : 56|8@1+ (1,0) [0|255] ""  PC

BO_ 2332749460 M2P_SUMDATA10__04: 8 MBMU
 SG_ M2P_SbmuPst_SysMaxVolt_HvOn04 : 0|8@1+ (1,0) [0|255] ""  PC
 SG_ M2P_CscPst_SysMaxVolt_HvOn04 : 8|8@1+ (1,0) [0|255] ""  PC
 SG_ M2P_CellPst_SysMaxVolt_HvOn04 : 16|8@1+ (1,0) [0|255] ""  PC
 SG_ M2P_SbmuPst_SysMinVolt_HvOn04 : 24|8@1+ (1,0) [0|255] ""  PC
 SG_ M2P_CscPst_SysMinVolt_HvOn04 : 32|8@1+ (1,0) [0|255] ""  PC
 SG_ M2P_CellPst_SysMinVolt_HvOn04 : 40|8@1+ (1,0) [0|255] ""  PC
 SG_ M2P_SbmuPst_SysMaxTemp_LvOn04 : 48|8@1+ (1,0) [0|255] ""  PC
 SG_ M2P_CscPst_SysMaxTemp_LvOn04 : 56|8@1+ (1,0) [0|255] ""  PC

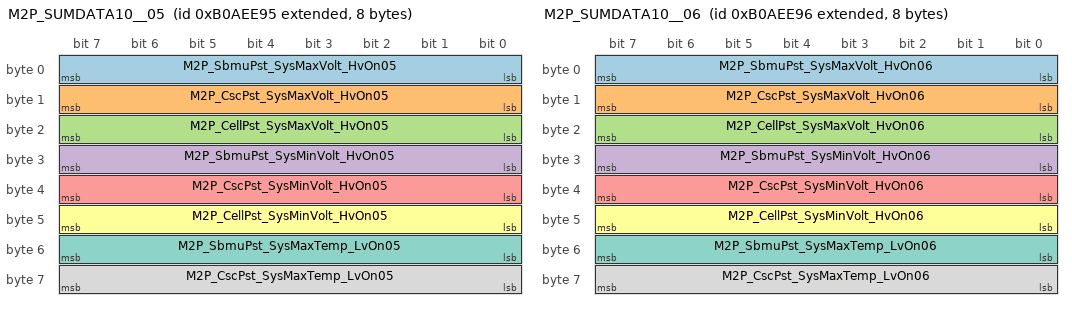
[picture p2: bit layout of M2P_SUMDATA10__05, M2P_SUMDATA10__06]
BO_ 2332749461 M2P_SUMDATA10__05: 8 MBMU
 SG_ M2P_SbmuPst_SysMaxVolt_HvOn05 : 0|8@1+ (1,0) [0|255] ""  PC
 SG_ M2P_CscPst_SysMaxVolt_HvOn05 : 8|8@1+ (1,0) [0|255] ""  PC
 SG_ M2P_CellPst_SysMaxVolt_HvOn05 : 16|8@1+ (1,0) [0|255] ""  PC
 SG_ M2P_SbmuPst_SysMinVolt_HvOn05 : 24|8@1+ (1,0) [0|255] ""  PC
 SG_ M2P_CscPst_SysMinVolt_HvOn05 : 32|8@1+ (1,0) [0|255] ""  PC
 SG_ M2P_CellPst_SysMinVolt_HvOn05 : 40|8@1+ (1,0) [0|255] ""  PC
 SG_ M2P_SbmuPst_SysMaxTemp_LvOn05 : 48|8@1+ (1,0) [0|255] ""  PC
 SG_ M2P_CscPst_SysMaxTemp_LvOn05 : 56|8@1+ (1,0) [0|255] ""  PC

BO_ 2332749462 M2P_SUMDATA10__06: 8 MBMU
 SG_ M2P_SbmuPst_SysMaxVolt_HvOn06 : 0|8@1+ (1,0) [0|255] ""  PC
 SG_ M2P_CscPst_SysMaxVolt_HvOn06 : 8|8@1+ (1,0) [0|255] ""  PC
 SG_ M2P_CellPst_SysMaxVolt_HvOn06 : 16|8@1+ (1,0) [0|255] ""  PC
 SG_ M2P_SbmuPst_SysMinVolt_HvOn06 : 24|8@1+ (1,0) [0|255] ""  PC
 SG_ M2P_CscPst_SysMinVolt_HvOn06 : 32|8@1+ (1,0) [0|255] ""  PC
 SG_ M2P_CellPst_SysMinVolt_HvOn06 : 40|8@1+ (1,0) [0|255] ""  PC
 SG_ M2P_SbmuPst_SysMaxTemp_LvOn06 : 48|8@1+ (1,0) [0|255] ""  PC
 SG_ M2P_CscPst_SysMaxTemp_LvOn06 : 56|8@1+ (1,0) [0|255] ""  PC

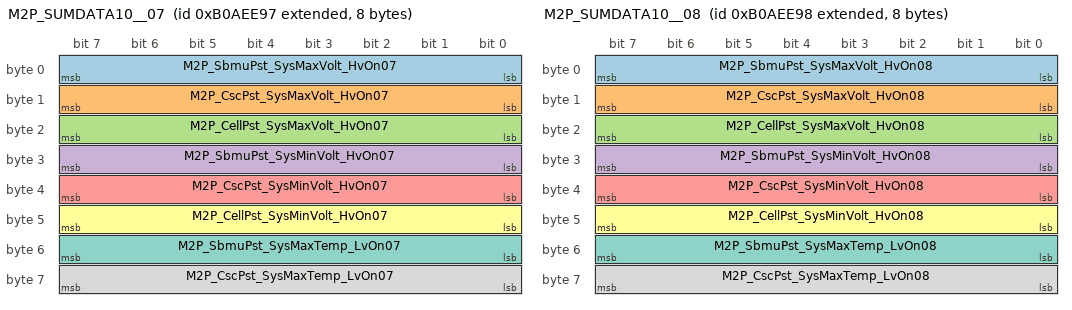
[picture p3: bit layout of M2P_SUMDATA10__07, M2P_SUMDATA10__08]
BO_ 2332749463 M2P_SUMDATA10__07: 8 MBMU
 SG_ M2P_SbmuPst_SysMaxVolt_HvOn07 : 0|8@1+ (1,0) [0|255] ""  PC
 SG_ M2P_CscPst_SysMaxVolt_HvOn07 : 8|8@1+ (1,0) [0|255] ""  PC
 SG_ M2P_CellPst_SysMaxVolt_HvOn07 : 16|8@1+ (1,0) [0|255] ""  PC
 SG_ M2P_SbmuPst_SysMinVolt_HvOn07 : 24|8@1+ (1,0) [0|255] ""  PC
 SG_ M2P_CscPst_SysMinVolt_HvOn07 : 32|8@1+ (1,0) [0|255] ""  PC
 SG_ M2P_CellPst_SysMinVolt_HvOn07 : 40|8@1+ (1,0) [0|255] ""  PC
 SG_ M2P_SbmuPst_SysMaxTemp_LvOn07 : 48|8@1+ (1,0) [0|255] ""  PC
 SG_ M2P_CscPst_SysMaxTemp_LvOn07 : 56|8@1+ (1,0) [0|255] ""  PC

BO_ 2332749464 M2P_SUMDATA10__08: 8 MBMU
 SG_ M2P_SbmuPst_SysMaxVolt_HvOn08 : 0|8@1+ (1,0) [0|255] ""  PC
 SG_ M2P_CscPst_SysMaxVolt_HvOn08 : 8|8@1+ (1,0) [0|255] ""  PC
 SG_ M2P_CellPst_SysMaxVolt_HvOn08 : 16|8@1+ (1,0) [0|255] ""  PC
 SG_ M2P_SbmuPst_SysMinVolt_HvOn08 : 24|8@1+ (1,0) [0|255] ""  PC
 SG_ M2P_CscPst_SysMinVolt_HvOn08 : 32|8@1+ (1,0) [0|255] ""  PC
 SG_ M2P_CellPst_SysMinVolt_HvOn08 : 40|8@1+ (1,0) [0|255] ""  PC
 SG_ M2P_SbmuPst_SysMaxTemp_LvOn08 : 48|8@1+ (1,0) [0|255] ""  PC
 SG_ M2P_CscPst_SysMaxTemp_LvOn08 : 56|8@1+ (1,0) [0|255] ""  PC

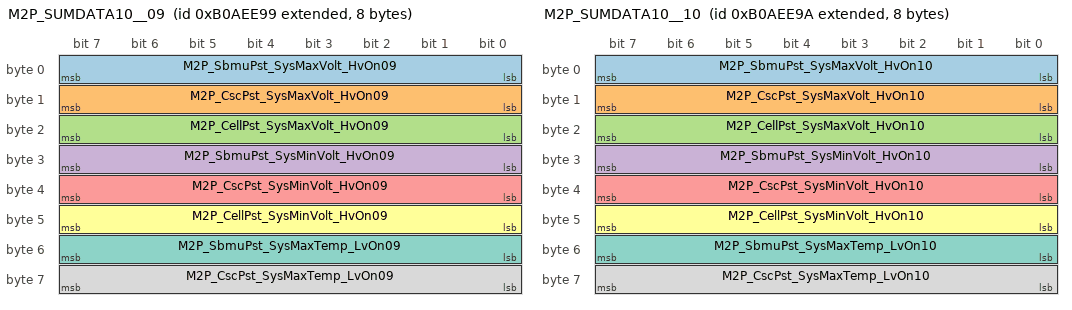
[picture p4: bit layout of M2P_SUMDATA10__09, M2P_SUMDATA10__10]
BO_ 2332749465 M2P_SUMDATA10__09: 8 MBMU
 SG_ M2P_SbmuPst_SysMaxVolt_HvOn09 : 0|8@1+ (1,0) [0|255] ""  PC
 SG_ M2P_CscPst_SysMaxVolt_HvOn09 : 8|8@1+ (1,0) [0|255] ""  PC
 SG_ M2P_CellPst_SysMaxVolt_HvOn09 : 16|8@1+ (1,0) [0|255] ""  PC
 SG_ M2P_SbmuPst_SysMinVolt_HvOn09 : 24|8@1+ (1,0) [0|255] ""  PC
 SG_ M2P_CscPst_SysMinVolt_HvOn09 : 32|8@1+ (1,0) [0|255] ""  PC
 SG_ M2P_CellPst_SysMinVolt_HvOn09 : 40|8@1+ (1,0) [0|255] ""  PC
 SG_ M2P_SbmuPst_SysMaxTemp_LvOn09 : 48|8@1+ (1,0) [0|255] ""  PC
 SG_ M2P_CscPst_SysMaxTemp_LvOn09 : 56|8@1+ (1,0) [0|255] ""  PC

BO_ 2332749466 M2P_SUMDATA10__10: 8 MBMU
 SG_ M2P_SbmuPst_SysMaxVolt_HvOn10 : 0|8@1+ (1,0) [0|255] ""  PC
 SG_ M2P_CscPst_SysMaxVolt_HvOn10 : 8|8@1+ (1,0) [0|255] ""  PC
 SG_ M2P_CellPst_SysMaxVolt_HvOn10 : 16|8@1+ (1,0) [0|255] ""  PC
 SG_ M2P_SbmuPst_SysMinVolt_HvOn10 : 24|8@1+ (1,0) [0|255] ""  PC
 SG_ M2P_CscPst_SysMinVolt_HvOn10 : 32|8@1+ (1,0) [0|255] ""  PC
 SG_ M2P_CellPst_SysMinVolt_HvOn10 : 40|8@1+ (1,0) [0|255] ""  PC
 SG_ M2P_SbmuPst_SysMaxTemp_LvOn10 : 48|8@1+ (1,0) [0|255] ""  PC
 SG_ M2P_CscPst_SysMaxTemp_LvOn10 : 56|8@1+ (1,0) [0|255] ""  PC

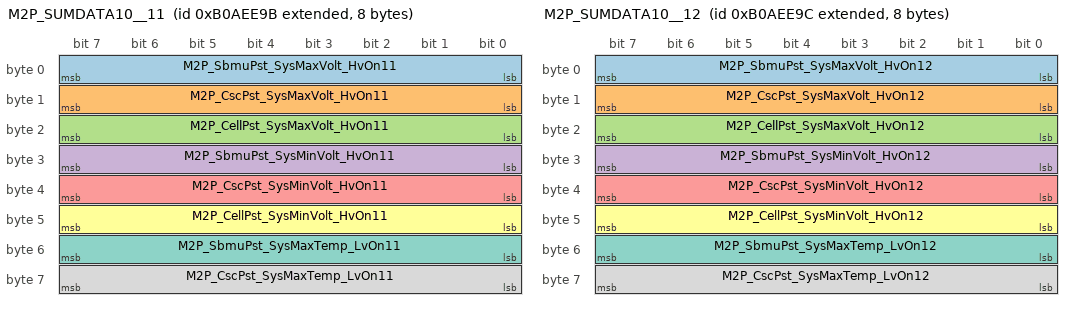
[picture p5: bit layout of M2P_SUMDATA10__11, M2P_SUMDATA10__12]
BO_ 2332749467 M2P_SUMDATA10__11: 8 MBMU
 SG_ M2P_SbmuPst_SysMaxVolt_HvOn11 : 0|8@1+ (1,0) [0|255] ""  PC
 SG_ M2P_CscPst_SysMaxVolt_HvOn11 : 8|8@1+ (1,0) [0|255] ""  PC
 SG_ M2P_CellPst_SysMaxVolt_HvOn11 : 16|8@1+ (1,0) [0|255] ""  PC
 SG_ M2P_SbmuPst_SysMinVolt_HvOn11 : 24|8@1+ (1,0) [0|255] ""  PC
 SG_ M2P_CscPst_SysMinVolt_HvOn11 : 32|8@1+ (1,0) [0|255] ""  PC
 SG_ M2P_CellPst_SysMinVolt_HvOn11 : 40|8@1+ (1,0) [0|255] ""  PC
 SG_ M2P_SbmuPst_SysMaxTemp_LvOn11 : 48|8@1+ (1,0) [0|255] ""  PC
 SG_ M2P_CscPst_SysMaxTemp_LvOn11 : 56|8@1+ (1,0) [0|255] ""  PC

BO_ 2332749468 M2P_SUMDATA10__12: 8 MBMU
 SG_ M2P_SbmuPst_SysMaxVolt_HvOn12 : 0|8@1+ (1,0) [0|255] ""  PC
 SG_ M2P_CscPst_SysMaxVolt_HvOn12 : 8|8@1+ (1,0) [0|255] ""  PC
 SG_ M2P_CellPst_SysMaxVolt_HvOn12 : 16|8@1+ (1,0) [0|255] ""  PC
 SG_ M2P_SbmuPst_SysMinVolt_HvOn12 : 24|8@1+ (1,0) [0|255] ""  PC
 SG_ M2P_CscPst_SysMinVolt_HvOn12 : 32|8@1+ (1,0) [0|255] ""  PC
 SG_ M2P_CellPst_SysMinVolt_HvOn12 : 40|8@1+ (1,0) [0|255] ""  PC
 SG_ M2P_SbmuPst_SysMaxTemp_LvOn12 : 48|8@1+ (1,0) [0|255] ""  PC
 SG_ M2P_CscPst_SysMaxTemp_LvOn12 : 56|8@1+ (1,0) [0|255] ""  PC

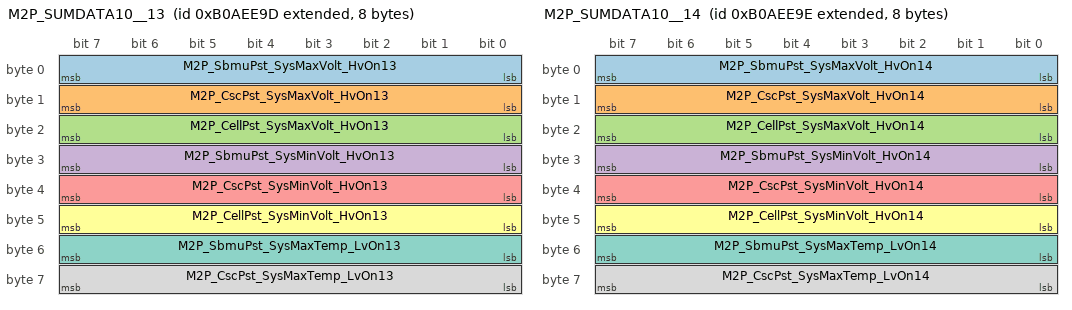
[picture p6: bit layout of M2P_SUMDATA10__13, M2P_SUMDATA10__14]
BO_ 2332749469 M2P_SUMDATA10__13: 8 MBMU
 SG_ M2P_SbmuPst_SysMaxVolt_HvOn13 : 0|8@1+ (1,0) [0|255] ""  PC
 SG_ M2P_CscPst_SysMaxVolt_HvOn13 : 8|8@1+ (1,0) [0|255] ""  PC
 SG_ M2P_CellPst_SysMaxVolt_HvOn13 : 16|8@1+ (1,0) [0|255] ""  PC
 SG_ M2P_SbmuPst_SysMinVolt_HvOn13 : 24|8@1+ (1,0) [0|255] ""  PC
 SG_ M2P_CscPst_SysMinVolt_HvOn13 : 32|8@1+ (1,0) [0|255] ""  PC
 SG_ M2P_CellPst_SysMinVolt_HvOn13 : 40|8@1+ (1,0) [0|255] ""  PC
 SG_ M2P_SbmuPst_SysMaxTemp_LvOn13 : 48|8@1+ (1,0) [0|255] ""  PC
 SG_ M2P_CscPst_SysMaxTemp_LvOn13 : 56|8@1+ (1,0) [0|255] ""  PC

BO_ 2332749470 M2P_SUMDATA10__14: 8 MBMU
 SG_ M2P_SbmuPst_SysMaxVolt_HvOn14 : 0|8@1+ (1,0) [0|255] ""  PC
 SG_ M2P_CscPst_SysMaxVolt_HvOn14 : 8|8@1+ (1,0) [0|255] ""  PC
 SG_ M2P_CellPst_SysMaxVolt_HvOn14 : 16|8@1+ (1,0) [0|255] ""  PC
 SG_ M2P_SbmuPst_SysMinVolt_HvOn14 : 24|8@1+ (1,0) [0|255] ""  PC
 SG_ M2P_CscPst_SysMinVolt_HvOn14 : 32|8@1+ (1,0) [0|255] ""  PC
 SG_ M2P_CellPst_SysMinVolt_HvOn14 : 40|8@1+ (1,0) [0|255] ""  PC
 SG_ M2P_SbmuPst_SysMaxTemp_LvOn14 : 48|8@1+ (1,0) [0|255] ""  PC
 SG_ M2P_CscPst_SysMaxTemp_LvOn14 : 56|8@1+ (1,0) [0|255] ""  PC

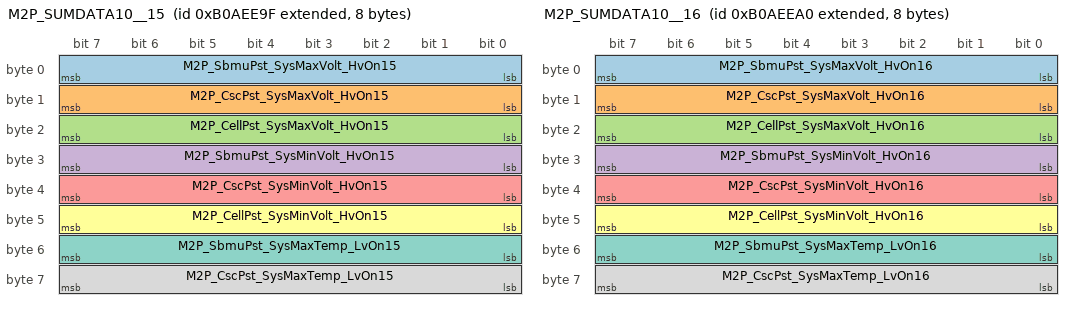
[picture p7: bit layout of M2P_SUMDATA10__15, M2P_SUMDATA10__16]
BO_ 2332749471 M2P_SUMDATA10__15: 8 MBMU
 SG_ M2P_SbmuPst_SysMaxVolt_HvOn15 : 0|8@1+ (1,0) [0|255] ""  PC
 SG_ M2P_CscPst_SysMaxVolt_HvOn15 : 8|8@1+ (1,0) [0|255] ""  PC
 SG_ M2P_CellPst_SysMaxVolt_HvOn15 : 16|8@1+ (1,0) [0|255] ""  PC
 SG_ M2P_SbmuPst_SysMinVolt_HvOn15 : 24|8@1+ (1,0) [0|255] ""  PC
 SG_ M2P_CscPst_SysMinVolt_HvOn15 : 32|8@1+ (1,0) [0|255] ""  PC
 SG_ M2P_CellPst_SysMinVolt_HvOn15 : 40|8@1+ (1,0) [0|255] ""  PC
 SG_ M2P_SbmuPst_SysMaxTemp_LvOn15 : 48|8@1+ (1,0) [0|255] ""  PC
 SG_ M2P_CscPst_SysMaxTemp_LvOn15 : 56|8@1+ (1,0) [0|255] ""  PC

BO_ 2332749472 M2P_SUMDATA10__16: 8 MBMU
 SG_ M2P_SbmuPst_SysMaxVolt_HvOn16 : 0|8@1+ (1,0) [0|255] ""  PC
 SG_ M2P_CscPst_SysMaxVolt_HvOn16 : 8|8@1+ (1,0) [0|255] ""  PC
 SG_ M2P_CellPst_SysMaxVolt_HvOn16 : 16|8@1+ (1,0) [0|255] ""  PC
 SG_ M2P_SbmuPst_SysMinVolt_HvOn16 : 24|8@1+ (1,0) [0|255] ""  PC
 SG_ M2P_CscPst_SysMinVolt_HvOn16 : 32|8@1+ (1,0) [0|255] ""  PC
 SG_ M2P_CellPst_SysMinVolt_HvOn16 : 40|8@1+ (1,0) [0|255] ""  PC
 SG_ M2P_SbmuPst_SysMaxTemp_LvOn16 : 48|8@1+ (1,0) [0|255] ""  PC
 SG_ M2P_CscPst_SysMaxTemp_LvOn16 : 56|8@1+ (1,0) [0|255] ""  PC

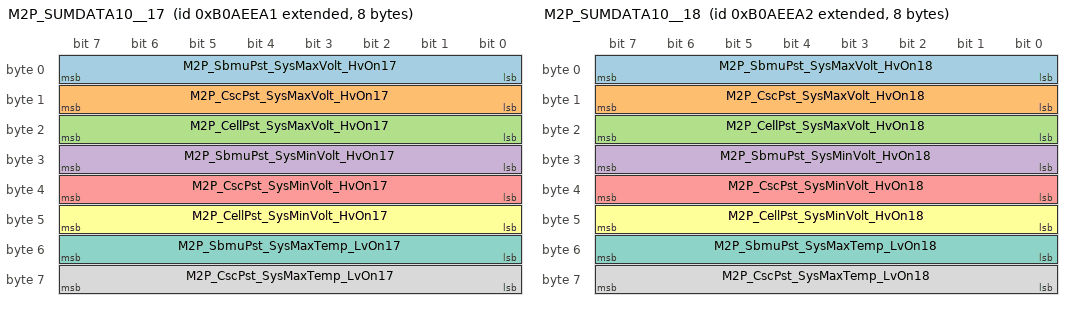
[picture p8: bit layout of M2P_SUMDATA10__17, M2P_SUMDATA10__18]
BO_ 2332749473 M2P_SUMDATA10__17: 8 MBMU
 SG_ M2P_SbmuPst_SysMaxVolt_HvOn17 : 0|8@1+ (1,0) [0|255] ""  PC
 SG_ M2P_CscPst_SysMaxVolt_HvOn17 : 8|8@1+ (1,0) [0|255] ""  PC
 SG_ M2P_CellPst_SysMaxVolt_HvOn17 : 16|8@1+ (1,0) [0|255] ""  PC
 SG_ M2P_SbmuPst_SysMinVolt_HvOn17 : 24|8@1+ (1,0) [0|255] ""  PC
 SG_ M2P_CscPst_SysMinVolt_HvOn17 : 32|8@1+ (1,0) [0|255] ""  PC
 SG_ M2P_CellPst_SysMinVolt_HvOn17 : 40|8@1+ (1,0) [0|255] ""  PC
 SG_ M2P_SbmuPst_SysMaxTemp_LvOn17 : 48|8@1+ (1,0) [0|255] ""  PC
 SG_ M2P_CscPst_SysMaxTemp_LvOn17 : 56|8@1+ (1,0) [0|255] ""  PC

BO_ 2332749474 M2P_SUMDATA10__18: 8 MBMU
 SG_ M2P_SbmuPst_SysMaxVolt_HvOn18 : 0|8@1+ (1,0) [0|255] ""  PC
 SG_ M2P_CscPst_SysMaxVolt_HvOn18 : 8|8@1+ (1,0) [0|255] ""  PC
 SG_ M2P_CellPst_SysMaxVolt_HvOn18 : 16|8@1+ (1,0) [0|255] ""  PC
 SG_ M2P_SbmuPst_SysMinVolt_HvOn18 : 24|8@1+ (1,0) [0|255] ""  PC
 SG_ M2P_CscPst_SysMinVolt_HvOn18 : 32|8@1+ (1,0) [0|255] ""  PC
 SG_ M2P_CellPst_SysMinVolt_HvOn18 : 40|8@1+ (1,0) [0|255] ""  PC
 SG_ M2P_SbmuPst_SysMaxTemp_LvOn18 : 48|8@1+ (1,0) [0|255] ""  PC
 SG_ M2P_CscPst_SysMaxTemp_LvOn18 : 56|8@1+ (1,0) [0|255] ""  PC

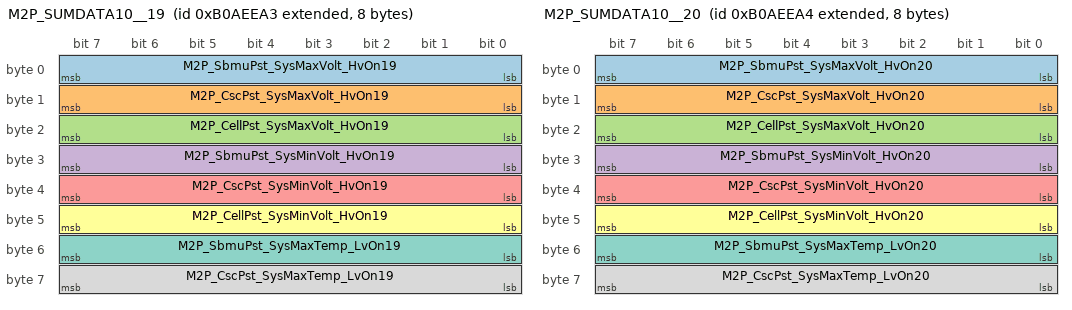
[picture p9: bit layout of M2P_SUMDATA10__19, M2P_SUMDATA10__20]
BO_ 2332749475 M2P_SUMDATA10__19: 8 MBMU
 SG_ M2P_SbmuPst_SysMaxVolt_HvOn19 : 0|8@1+ (1,0) [0|255] ""  PC
 SG_ M2P_CscPst_SysMaxVolt_HvOn19 : 8|8@1+ (1,0) [0|255] ""  PC
 SG_ M2P_CellPst_SysMaxVolt_HvOn19 : 16|8@1+ (1,0) [0|255] ""  PC
 SG_ M2P_SbmuPst_SysMinVolt_HvOn19 : 24|8@1+ (1,0) [0|255] ""  PC
 SG_ M2P_CscPst_SysMinVolt_HvOn19 : 32|8@1+ (1,0) [0|255] ""  PC
 SG_ M2P_CellPst_SysMinVolt_HvOn19 : 40|8@1+ (1,0) [0|255] ""  PC
 SG_ M2P_SbmuPst_SysMaxTemp_LvOn19 : 48|8@1+ (1,0) [0|255] ""  PC
 SG_ M2P_CscPst_SysMaxTemp_LvOn19 : 56|8@1+ (1,0) [0|255] ""  PC

BO_ 2332749476 M2P_SUMDATA10__20: 8 MBMU
 SG_ M2P_SbmuPst_SysMaxVolt_HvOn20 : 0|8@1+ (1,0) [0|255] ""  PC
 SG_ M2P_CscPst_SysMaxVolt_HvOn20 : 8|8@1+ (1,0) [0|255] ""  PC
 SG_ M2P_CellPst_SysMaxVolt_HvOn20 : 16|8@1+ (1,0) [0|255] ""  PC
 SG_ M2P_SbmuPst_SysMinVolt_HvOn20 : 24|8@1+ (1,0) [0|255] ""  PC
 SG_ M2P_CscPst_SysMinVolt_HvOn20 : 32|8@1+ (1,0) [0|255] ""  PC
 SG_ M2P_CellPst_SysMinVolt_HvOn20 : 40|8@1+ (1,0) [0|255] ""  PC
 SG_ M2P_SbmuPst_SysMaxTemp_LvOn20 : 48|8@1+ (1,0) [0|255] ""  PC
 SG_ M2P_CscPst_SysMaxTemp_LvOn20 : 56|8@1+ (1,0) [0|255] ""  PC

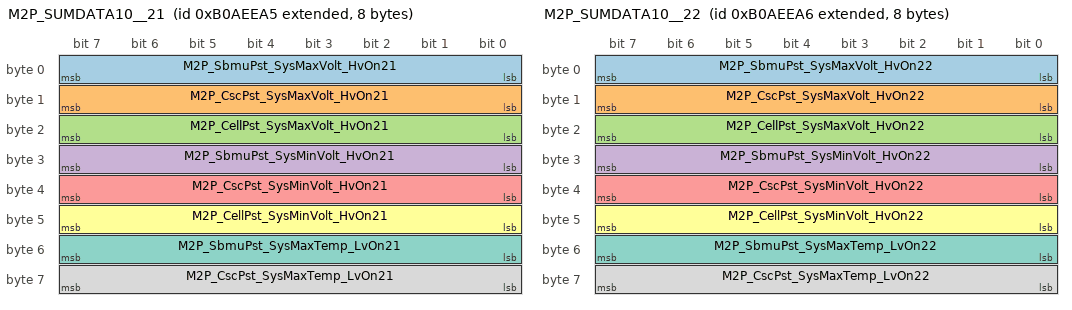
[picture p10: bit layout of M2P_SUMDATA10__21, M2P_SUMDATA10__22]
BO_ 2332749477 M2P_SUMDATA10__21: 8 MBMU
 SG_ M2P_SbmuPst_SysMaxVolt_HvOn21 : 0|8@1+ (1,0) [0|255] ""  PC
 SG_ M2P_CscPst_SysMaxVolt_HvOn21 : 8|8@1+ (1,0) [0|255] ""  PC
 SG_ M2P_CellPst_SysMaxVolt_HvOn21 : 16|8@1+ (1,0) [0|255] ""  PC
 SG_ M2P_SbmuPst_SysMinVolt_HvOn21 : 24|8@1+ (1,0) [0|255] ""  PC
 SG_ M2P_CscPst_SysMinVolt_HvOn21 : 32|8@1+ (1,0) [0|255] ""  PC
 SG_ M2P_CellPst_SysMinVolt_HvOn21 : 40|8@1+ (1,0) [0|255] ""  PC
 SG_ M2P_SbmuPst_SysMaxTemp_LvOn21 : 48|8@1+ (1,0) [0|255] ""  PC
 SG_ M2P_CscPst_SysMaxTemp_LvOn21 : 56|8@1+ (1,0) [0|255] ""  PC

BO_ 2332749478 M2P_SUMDATA10__22: 8 MBMU
 SG_ M2P_SbmuPst_SysMaxVolt_HvOn22 : 0|8@1+ (1,0) [0|255] ""  PC
 SG_ M2P_CscPst_SysMaxVolt_HvOn22 : 8|8@1+ (1,0) [0|255] ""  PC
 SG_ M2P_CellPst_SysMaxVolt_HvOn22 : 16|8@1+ (1,0) [0|255] ""  PC
 SG_ M2P_SbmuPst_SysMinVolt_HvOn22 : 24|8@1+ (1,0) [0|255] ""  PC
 SG_ M2P_CscPst_SysMinVolt_HvOn22 : 32|8@1+ (1,0) [0|255] ""  PC
 SG_ M2P_CellPst_SysMinVolt_HvOn22 : 40|8@1+ (1,0) [0|255] ""  PC
 SG_ M2P_SbmuPst_SysMaxTemp_LvOn22 : 48|8@1+ (1,0) [0|255] ""  PC
 SG_ M2P_CscPst_SysMaxTemp_LvOn22 : 56|8@1+ (1,0) [0|255] ""  PC

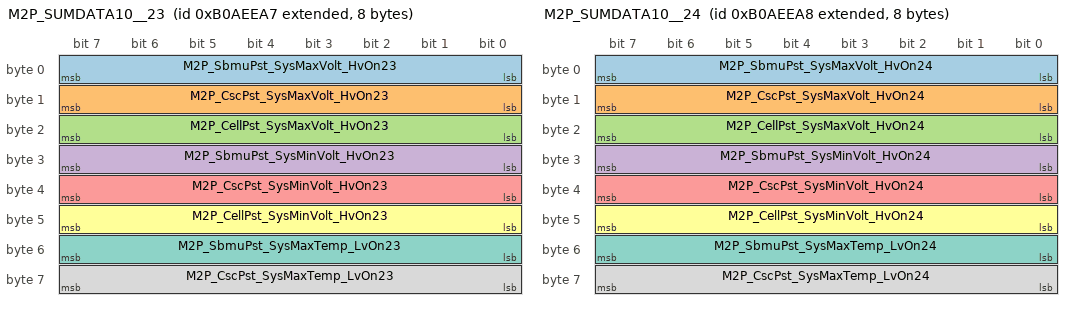
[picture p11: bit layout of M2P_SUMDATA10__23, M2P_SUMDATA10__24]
BO_ 2332749479 M2P_SUMDATA10__23: 8 MBMU
 SG_ M2P_SbmuPst_SysMaxVolt_HvOn23 : 0|8@1+ (1,0) [0|255] ""  PC
 SG_ M2P_CscPst_SysMaxVolt_HvOn23 : 8|8@1+ (1,0) [0|255] ""  PC
 SG_ M2P_CellPst_SysMaxVolt_HvOn23 : 16|8@1+ (1,0) [0|255] ""  PC
 SG_ M2P_SbmuPst_SysMinVolt_HvOn23 : 24|8@1+ (1,0) [0|255] ""  PC
 SG_ M2P_CscPst_SysMinVolt_HvOn23 : 32|8@1+ (1,0) [0|255] ""  PC
 SG_ M2P_CellPst_SysMinVolt_HvOn23 : 40|8@1+ (1,0) [0|255] ""  PC
 SG_ M2P_SbmuPst_SysMaxTemp_LvOn23 : 48|8@1+ (1,0) [0|255] ""  PC
 SG_ M2P_CscPst_SysMaxTemp_LvOn23 : 56|8@1+ (1,0) [0|255] ""  PC

BO_ 2332749480 M2P_SUMDATA10__24: 8 MBMU
 SG_ M2P_SbmuPst_SysMaxVolt_HvOn24 : 0|8@1+ (1,0) [0|255] ""  PC
 SG_ M2P_CscPst_SysMaxVolt_HvOn24 : 8|8@1+ (1,0) [0|255] ""  PC
 SG_ M2P_CellPst_SysMaxVolt_HvOn24 : 16|8@1+ (1,0) [0|255] ""  PC
 SG_ M2P_SbmuPst_SysMinVolt_HvOn24 : 24|8@1+ (1,0) [0|255] ""  PC
 SG_ M2P_CscPst_SysMinVolt_HvOn24 : 32|8@1+ (1,0) [0|255] ""  PC
 SG_ M2P_CellPst_SysMinVolt_HvOn24 : 40|8@1+ (1,0) [0|255] ""  PC
 SG_ M2P_SbmuPst_SysMaxTemp_LvOn24 : 48|8@1+ (1,0) [0|255] ""  PC
 SG_ M2P_CscPst_SysMaxTemp_LvOn24 : 56|8@1+ (1,0) [0|255] ""  PC

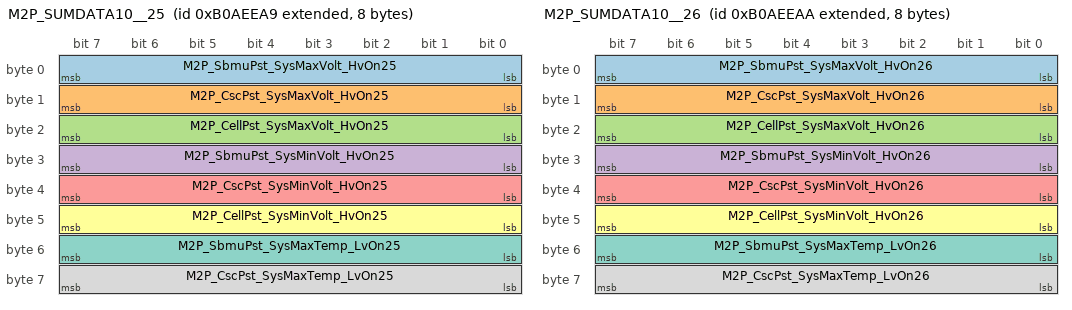
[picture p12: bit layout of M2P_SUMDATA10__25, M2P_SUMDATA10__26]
BO_ 2332749481 M2P_SUMDATA10__25: 8 MBMU
 SG_ M2P_SbmuPst_SysMaxVolt_HvOn25 : 0|8@1+ (1,0) [0|255] ""  PC
 SG_ M2P_CscPst_SysMaxVolt_HvOn25 : 8|8@1+ (1,0) [0|255] ""  PC
 SG_ M2P_CellPst_SysMaxVolt_HvOn25 : 16|8@1+ (1,0) [0|255] ""  PC
 SG_ M2P_SbmuPst_SysMinVolt_HvOn25 : 24|8@1+ (1,0) [0|255] ""  PC
 SG_ M2P_CscPst_SysMinVolt_HvOn25 : 32|8@1+ (1,0) [0|255] ""  PC
 SG_ M2P_CellPst_SysMinVolt_HvOn25 : 40|8@1+ (1,0) [0|255] ""  PC
 SG_ M2P_SbmuPst_SysMaxTemp_LvOn25 : 48|8@1+ (1,0) [0|255] ""  PC
 SG_ M2P_CscPst_SysMaxTemp_LvOn25 : 56|8@1+ (1,0) [0|255] ""  PC

BO_ 2332749482 M2P_SUMDATA10__26: 8 MBMU
 SG_ M2P_SbmuPst_SysMaxVolt_HvOn26 : 0|8@1+ (1,0) [0|255] ""  PC
 SG_ M2P_CscPst_SysMaxVolt_HvOn26 : 8|8@1+ (1,0) [0|255] ""  PC
 SG_ M2P_CellPst_SysMaxVolt_HvOn26 : 16|8@1+ (1,0) [0|255] ""  PC
 SG_ M2P_SbmuPst_SysMinVolt_HvOn26 : 24|8@1+ (1,0) [0|255] ""  PC
 SG_ M2P_CscPst_SysMinVolt_HvOn26 : 32|8@1+ (1,0) [0|255] ""  PC
 SG_ M2P_CellPst_SysMinVolt_HvOn26 : 40|8@1+ (1,0) [0|255] ""  PC
 SG_ M2P_SbmuPst_SysMaxTemp_LvOn26 : 48|8@1+ (1,0) [0|255] ""  PC
 SG_ M2P_CscPst_SysMaxTemp_LvOn26 : 56|8@1+ (1,0) [0|255] ""  PC

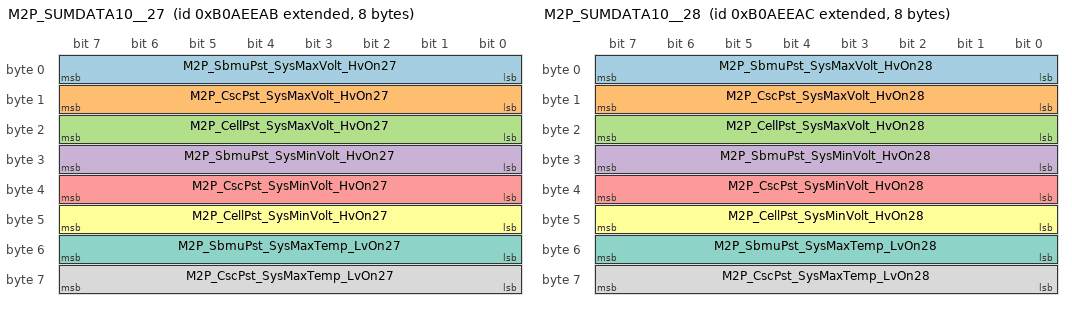
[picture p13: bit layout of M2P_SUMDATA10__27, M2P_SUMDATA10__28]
BO_ 2332749483 M2P_SUMDATA10__27: 8 MBMU
 SG_ M2P_SbmuPst_SysMaxVolt_HvOn27 : 0|8@1+ (1,0) [0|255] ""  PC
 SG_ M2P_CscPst_SysMaxVolt_HvOn27 : 8|8@1+ (1,0) [0|255] ""  PC
 SG_ M2P_CellPst_SysMaxVolt_HvOn27 : 16|8@1+ (1,0) [0|255] ""  PC
 SG_ M2P_SbmuPst_SysMinVolt_HvOn27 : 24|8@1+ (1,0) [0|255] ""  PC
 SG_ M2P_CscPst_SysMinVolt_HvOn27 : 32|8@1+ (1,0) [0|255] ""  PC
 SG_ M2P_CellPst_SysMinVolt_HvOn27 : 40|8@1+ (1,0) [0|255] ""  PC
 SG_ M2P_SbmuPst_SysMaxTemp_LvOn27 : 48|8@1+ (1,0) [0|255] ""  PC
 SG_ M2P_CscPst_SysMaxTemp_LvOn27 : 56|8@1+ (1,0) [0|255] ""  PC

BO_ 2332749484 M2P_SUMDATA10__28: 8 MBMU
 SG_ M2P_SbmuPst_SysMaxVolt_HvOn28 : 0|8@1+ (1,0) [0|255] ""  PC
 SG_ M2P_CscPst_SysMaxVolt_HvOn28 : 8|8@1+ (1,0) [0|255] ""  PC
 SG_ M2P_CellPst_SysMaxVolt_HvOn28 : 16|8@1+ (1,0) [0|255] ""  PC
 SG_ M2P_SbmuPst_SysMinVolt_HvOn28 : 24|8@1+ (1,0) [0|255] ""  PC
 SG_ M2P_CscPst_SysMinVolt_HvOn28 : 32|8@1+ (1,0) [0|255] ""  PC
 SG_ M2P_CellPst_SysMinVolt_HvOn28 : 40|8@1+ (1,0) [0|255] ""  PC
 SG_ M2P_SbmuPst_SysMaxTemp_LvOn28 : 48|8@1+ (1,0) [0|255] ""  PC
 SG_ M2P_CscPst_SysMaxTemp_LvOn28 : 56|8@1+ (1,0) [0|255] ""  PC

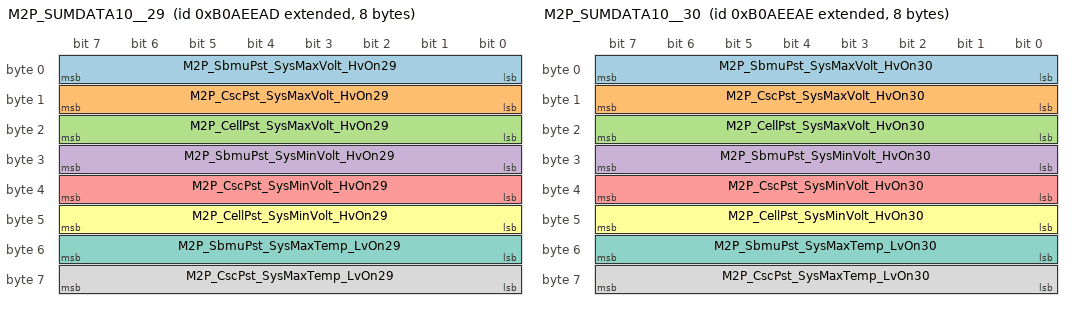
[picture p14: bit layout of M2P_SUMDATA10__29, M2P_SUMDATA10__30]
BO_ 2332749485 M2P_SUMDATA10__29: 8 MBMU
 SG_ M2P_SbmuPst_SysMaxVolt_HvOn29 : 0|8@1+ (1,0) [0|255] ""  PC
 SG_ M2P_CscPst_SysMaxVolt_HvOn29 : 8|8@1+ (1,0) [0|255] ""  PC
 SG_ M2P_CellPst_SysMaxVolt_HvOn29 : 16|8@1+ (1,0) [0|255] ""  PC
 SG_ M2P_SbmuPst_SysMinVolt_HvOn29 : 24|8@1+ (1,0) [0|255] ""  PC
 SG_ M2P_CscPst_SysMinVolt_HvOn29 : 32|8@1+ (1,0) [0|255] ""  PC
 SG_ M2P_CellPst_SysMinVolt_HvOn29 : 40|8@1+ (1,0) [0|255] ""  PC
 SG_ M2P_SbmuPst_SysMaxTemp_LvOn29 : 48|8@1+ (1,0) [0|255] ""  PC
 SG_ M2P_CscPst_SysMaxTemp_LvOn29 : 56|8@1+ (1,0) [0|255] ""  PC

BO_ 2332749486 M2P_SUMDATA10__30: 8 MBMU
 SG_ M2P_SbmuPst_SysMaxVolt_HvOn30 : 0|8@1+ (1,0) [0|255] ""  PC
 SG_ M2P_CscPst_SysMaxVolt_HvOn30 : 8|8@1+ (1,0) [0|255] ""  PC
 SG_ M2P_CellPst_SysMaxVolt_HvOn30 : 16|8@1+ (1,0) [0|255] ""  PC
 SG_ M2P_SbmuPst_SysMinVolt_HvOn30 : 24|8@1+ (1,0) [0|255] ""  PC
 SG_ M2P_CscPst_SysMinVolt_HvOn30 : 32|8@1+ (1,0) [0|255] ""  PC
 SG_ M2P_CellPst_SysMinVolt_HvOn30 : 40|8@1+ (1,0) [0|255] ""  PC
 SG_ M2P_SbmuPst_SysMaxTemp_LvOn30 : 48|8@1+ (1,0) [0|255] ""  PC
 SG_ M2P_CscPst_SysMaxTemp_LvOn30 : 56|8@1+ (1,0) [0|255] ""  PC

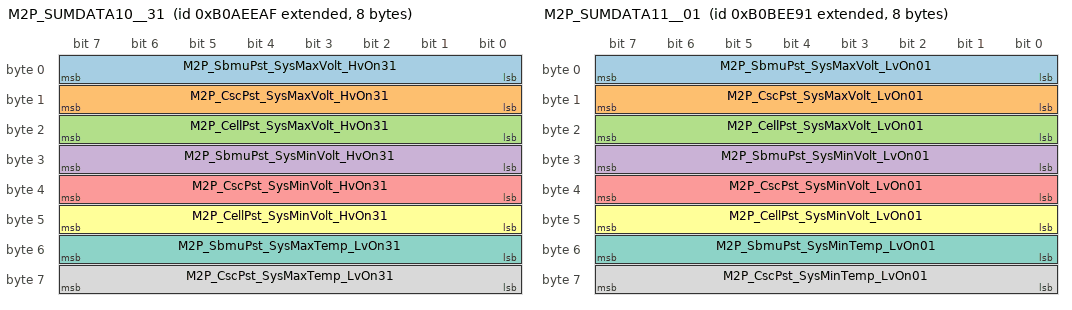
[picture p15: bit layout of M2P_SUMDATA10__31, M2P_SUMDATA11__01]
BO_ 2332749487 M2P_SUMDATA10__31: 8 MBMU
 SG_ M2P_SbmuPst_SysMaxVolt_HvOn31 : 0|8@1+ (1,0) [0|255] ""  PC
 SG_ M2P_CscPst_SysMaxVolt_HvOn31 : 8|8@1+ (1,0) [0|255] ""  PC
 SG_ M2P_CellPst_SysMaxVolt_HvOn31 : 16|8@1+ (1,0) [0|255] ""  PC
 SG_ M2P_SbmuPst_SysMinVolt_HvOn31 : 24|8@1+ (1,0) [0|255] ""  PC
 SG_ M2P_CscPst_SysMinVolt_HvOn31 : 32|8@1+ (1,0) [0|255] ""  PC
 SG_ M2P_CellPst_SysMinVolt_HvOn31 : 40|8@1+ (1,0) [0|255] ""  PC
 SG_ M2P_SbmuPst_SysMaxTemp_LvOn31 : 48|8@1+ (1,0) [0|255] ""  PC
 SG_ M2P_CscPst_SysMaxTemp_LvOn31 : 56|8@1+ (1,0) [0|255] ""  PC

BO_ 2332814993 M2P_SUMDATA11__01: 8 MBMU
 SG_ M2P_SbmuPst_SysMaxVolt_LvOn01 : 0|8@1+ (1,0) [0|255] ""  PC
 SG_ M2P_CscPst_SysMaxVolt_LvOn01 : 8|8@1+ (1,0) [0|255] ""  PC
 SG_ M2P_CellPst_SysMaxVolt_LvOn01 : 16|8@1+ (1,0) [0|255] ""  PC
 SG_ M2P_SbmuPst_SysMinVolt_LvOn01 : 24|8@1+ (1,0) [0|255] ""  PC
 SG_ M2P_CscPst_SysMinVolt_LvOn01 : 32|8@1+ (1,0) [0|255] ""  PC
 SG_ M2P_CellPst_SysMinVolt_LvOn01 : 40|8@1+ (1,0) [0|255] ""  PC
 SG_ M2P_SbmuPst_SysMinTemp_LvOn01 : 48|8@1+ (1,0) [0|255] ""  PC
 SG_ M2P_CscPst_SysMinTemp_LvOn01 : 56|8@1+ (1,0) [0|255] ""  PC

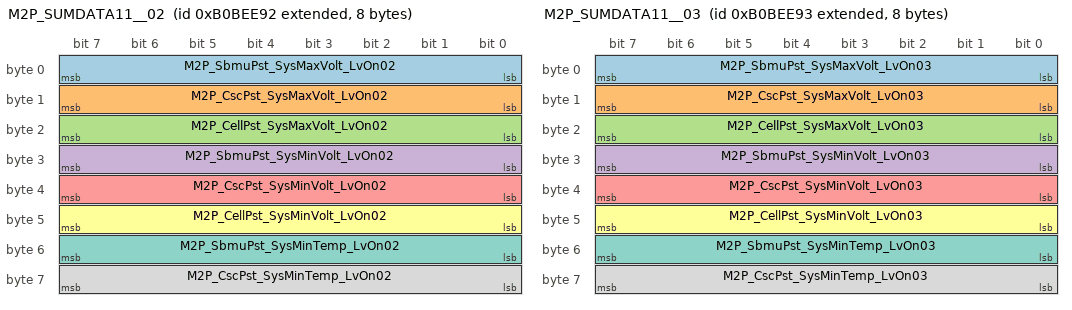
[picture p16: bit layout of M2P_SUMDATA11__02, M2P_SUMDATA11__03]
BO_ 2332814994 M2P_SUMDATA11__02: 8 MBMU
 SG_ M2P_SbmuPst_SysMaxVolt_LvOn02 : 0|8@1+ (1,0) [0|255] ""  PC
 SG_ M2P_CscPst_SysMaxVolt_LvOn02 : 8|8@1+ (1,0) [0|255] ""  PC
 SG_ M2P_CellPst_SysMaxVolt_LvOn02 : 16|8@1+ (1,0) [0|255] ""  PC
 SG_ M2P_SbmuPst_SysMinVolt_LvOn02 : 24|8@1+ (1,0) [0|255] ""  PC
 SG_ M2P_CscPst_SysMinVolt_LvOn02 : 32|8@1+ (1,0) [0|255] ""  PC
 SG_ M2P_CellPst_SysMinVolt_LvOn02 : 40|8@1+ (1,0) [0|255] ""  PC
 SG_ M2P_SbmuPst_SysMinTemp_LvOn02 : 48|8@1+ (1,0) [0|255] ""  PC
 SG_ M2P_CscPst_SysMinTemp_LvOn02 : 56|8@1+ (1,0) [0|255] ""  PC

BO_ 2332814995 M2P_SUMDATA11__03: 8 MBMU
 SG_ M2P_SbmuPst_SysMaxVolt_LvOn03 : 0|8@1+ (1,0) [0|255] ""  PC
 SG_ M2P_CscPst_SysMaxVolt_LvOn03 : 8|8@1+ (1,0) [0|255] ""  PC
 SG_ M2P_CellPst_SysMaxVolt_LvOn03 : 16|8@1+ (1,0) [0|255] ""  PC
 SG_ M2P_SbmuPst_SysMinVolt_LvOn03 : 24|8@1+ (1,0) [0|255] ""  PC
 SG_ M2P_CscPst_SysMinVolt_LvOn03 : 32|8@1+ (1,0) [0|255] ""  PC
 SG_ M2P_CellPst_SysMinVolt_LvOn03 : 40|8@1+ (1,0) [0|255] ""  PC
 SG_ M2P_SbmuPst_SysMinTemp_LvOn03 : 48|8@1+ (1,0) [0|255] ""  PC
 SG_ M2P_CscPst_SysMinTemp_LvOn03 : 56|8@1+ (1,0) [0|255] ""  PC

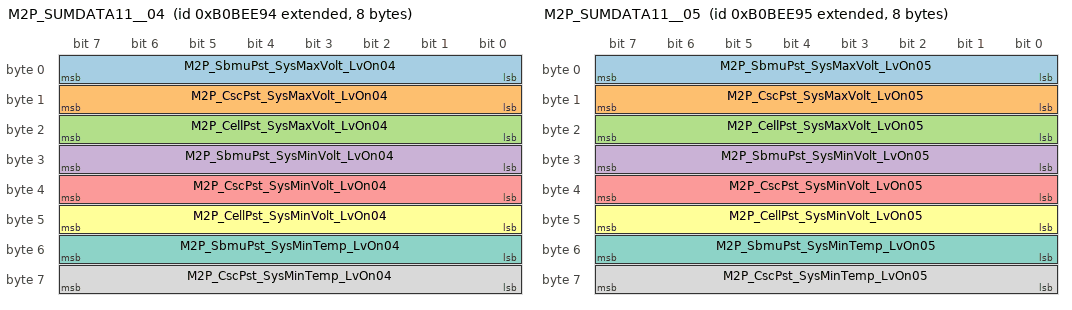
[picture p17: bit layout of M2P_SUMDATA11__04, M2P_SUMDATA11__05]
BO_ 2332814996 M2P_SUMDATA11__04: 8 MBMU
 SG_ M2P_SbmuPst_SysMaxVolt_LvOn04 : 0|8@1+ (1,0) [0|255] ""  PC
 SG_ M2P_CscPst_SysMaxVolt_LvOn04 : 8|8@1+ (1,0) [0|255] ""  PC
 SG_ M2P_CellPst_SysMaxVolt_LvOn04 : 16|8@1+ (1,0) [0|255] ""  PC
 SG_ M2P_SbmuPst_SysMinVolt_LvOn04 : 24|8@1+ (1,0) [0|255] ""  PC
 SG_ M2P_CscPst_SysMinVolt_LvOn04 : 32|8@1+ (1,0) [0|255] ""  PC
 SG_ M2P_CellPst_SysMinVolt_LvOn04 : 40|8@1+ (1,0) [0|255] ""  PC
 SG_ M2P_SbmuPst_SysMinTemp_LvOn04 : 48|8@1+ (1,0) [0|255] ""  PC
 SG_ M2P_CscPst_SysMinTemp_LvOn04 : 56|8@1+ (1,0) [0|255] ""  PC

BO_ 2332814997 M2P_SUMDATA11__05: 8 MBMU
 SG_ M2P_SbmuPst_SysMaxVolt_LvOn05 : 0|8@1+ (1,0) [0|255] ""  PC
 SG_ M2P_CscPst_SysMaxVolt_LvOn05 : 8|8@1+ (1,0) [0|255] ""  PC
 SG_ M2P_CellPst_SysMaxVolt_LvOn05 : 16|8@1+ (1,0) [0|255] ""  PC
 SG_ M2P_SbmuPst_SysMinVolt_LvOn05 : 24|8@1+ (1,0) [0|255] ""  PC
 SG_ M2P_CscPst_SysMinVolt_LvOn05 : 32|8@1+ (1,0) [0|255] ""  PC
 SG_ M2P_CellPst_SysMinVolt_LvOn05 : 40|8@1+ (1,0) [0|255] ""  PC
 SG_ M2P_SbmuPst_SysMinTemp_LvOn05 : 48|8@1+ (1,0) [0|255] ""  PC
 SG_ M2P_CscPst_SysMinTemp_LvOn05 : 56|8@1+ (1,0) [0|255] ""  PC

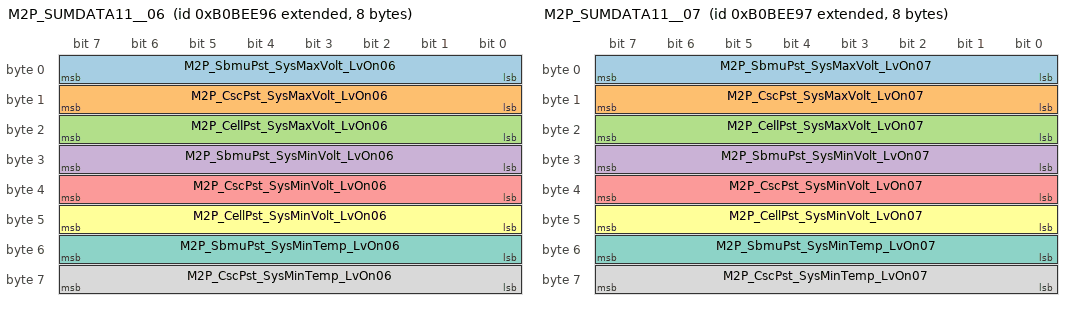
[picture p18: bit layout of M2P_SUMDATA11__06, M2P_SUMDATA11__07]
BO_ 2332814998 M2P_SUMDATA11__06: 8 MBMU
 SG_ M2P_SbmuPst_SysMaxVolt_LvOn06 : 0|8@1+ (1,0) [0|255] ""  PC
 SG_ M2P_CscPst_SysMaxVolt_LvOn06 : 8|8@1+ (1,0) [0|255] ""  PC
 SG_ M2P_CellPst_SysMaxVolt_LvOn06 : 16|8@1+ (1,0) [0|255] ""  PC
 SG_ M2P_SbmuPst_SysMinVolt_LvOn06 : 24|8@1+ (1,0) [0|255] ""  PC
 SG_ M2P_CscPst_SysMinVolt_LvOn06 : 32|8@1+ (1,0) [0|255] ""  PC
 SG_ M2P_CellPst_SysMinVolt_LvOn06 : 40|8@1+ (1,0) [0|255] ""  PC
 SG_ M2P_SbmuPst_SysMinTemp_LvOn06 : 48|8@1+ (1,0) [0|255] ""  PC
 SG_ M2P_CscPst_SysMinTemp_LvOn06 : 56|8@1+ (1,0) [0|255] ""  PC

BO_ 2332814999 M2P_SUMDATA11__07: 8 MBMU
 SG_ M2P_SbmuPst_SysMaxVolt_LvOn07 : 0|8@1+ (1,0) [0|255] ""  PC
 SG_ M2P_CscPst_SysMaxVolt_LvOn07 : 8|8@1+ (1,0) [0|255] ""  PC
 SG_ M2P_CellPst_SysMaxVolt_LvOn07 : 16|8@1+ (1,0) [0|255] ""  PC
 SG_ M2P_SbmuPst_SysMinVolt_LvOn07 : 24|8@1+ (1,0) [0|255] ""  PC
 SG_ M2P_CscPst_SysMinVolt_LvOn07 : 32|8@1+ (1,0) [0|255] ""  PC
 SG_ M2P_CellPst_SysMinVolt_LvOn07 : 40|8@1+ (1,0) [0|255] ""  PC
 SG_ M2P_SbmuPst_SysMinTemp_LvOn07 : 48|8@1+ (1,0) [0|255] ""  PC
 SG_ M2P_CscPst_SysMinTemp_LvOn07 : 56|8@1+ (1,0) [0|255] ""  PC

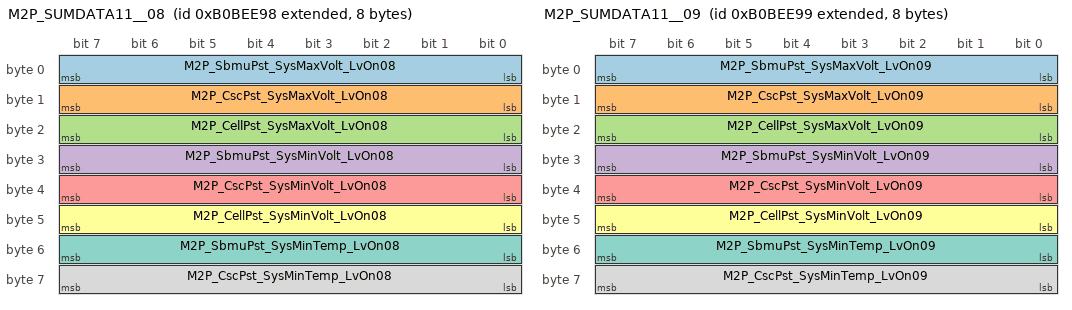
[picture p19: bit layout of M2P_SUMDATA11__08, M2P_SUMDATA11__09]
BO_ 2332815000 M2P_SUMDATA11__08: 8 MBMU
 SG_ M2P_SbmuPst_SysMaxVolt_LvOn08 : 0|8@1+ (1,0) [0|255] ""  PC
 SG_ M2P_CscPst_SysMaxVolt_LvOn08 : 8|8@1+ (1,0) [0|255] ""  PC
 SG_ M2P_CellPst_SysMaxVolt_LvOn08 : 16|8@1+ (1,0) [0|255] ""  PC
 SG_ M2P_SbmuPst_SysMinVolt_LvOn08 : 24|8@1+ (1,0) [0|255] ""  PC
 SG_ M2P_CscPst_SysMinVolt_LvOn08 : 32|8@1+ (1,0) [0|255] ""  PC
 SG_ M2P_CellPst_SysMinVolt_LvOn08 : 40|8@1+ (1,0) [0|255] ""  PC
 SG_ M2P_SbmuPst_SysMinTemp_LvOn08 : 48|8@1+ (1,0) [0|255] ""  PC
 SG_ M2P_CscPst_SysMinTemp_LvOn08 : 56|8@1+ (1,0) [0|255] ""  PC

BO_ 2332815001 M2P_SUMDATA11__09: 8 MBMU
 SG_ M2P_SbmuPst_SysMaxVolt_LvOn09 : 0|8@1+ (1,0) [0|255] ""  PC
 SG_ M2P_CscPst_SysMaxVolt_LvOn09 : 8|8@1+ (1,0) [0|255] ""  PC
 SG_ M2P_CellPst_SysMaxVolt_LvOn09 : 16|8@1+ (1,0) [0|255] ""  PC
 SG_ M2P_SbmuPst_SysMinVolt_LvOn09 : 24|8@1+ (1,0) [0|255] ""  PC
 SG_ M2P_CscPst_SysMinVolt_LvOn09 : 32|8@1+ (1,0) [0|255] ""  PC
 SG_ M2P_CellPst_SysMinVolt_LvOn09 : 40|8@1+ (1,0) [0|255] ""  PC
 SG_ M2P_SbmuPst_SysMinTemp_LvOn09 : 48|8@1+ (1,0) [0|255] ""  PC
 SG_ M2P_CscPst_SysMinTemp_LvOn09 : 56|8@1+ (1,0) [0|255] ""  PC

BO_ 2332815002 M2P_SUMDATA11__10: 8 MBMU
 SG_ M2P_SbmuPst_SysMaxVolt_LvOn10 : 0|8@1+ (1,0) [0|255] ""  PC
 SG_ M2P_CscPst_SysMaxVolt_LvOn10 : 8|8@1+ (1,0) [0|255] ""  PC
 SG_ M2P_CellPst_SysMaxVolt_LvOn10 : 16|8@1+ (1,0) [0|255] ""  PC
 SG_ M2P_SbmuPst_SysMinVolt_LvOn10 : 24|8@1+ (1,0) [0|255] ""  PC
 SG_ M2P_CscPst_SysMinVolt_LvOn10 : 32|8@1+ (1,0) [0|255] ""  PC
 SG_ M2P_CellPst_SysMinVolt_LvOn10 : 40|8@1+ (1,0) [0|255] ""  PC
 SG_ M2P_SbmuPst_SysMinTemp_LvOn10 : 48|8@1+ (1,0) [0|255] ""  PC
 SG_ M2P_CscPst_SysMinTemp_LvOn10 : 56|8@1+ (1,0) [0|255] ""  PC

BO_ 2332815003 M2P_SUMDATA11__11: 8 MBMU
 SG_ M2P_SbmuPst_SysMaxVolt_LvOn11 : 0|8@1+ (1,0) [0|255] ""  PC
 SG_ M2P_CscPst_SysMaxVolt_LvOn11 : 8|8@1+ (1,0) [0|255] ""  PC
 SG_ M2P_CellPst_SysMaxVolt_LvOn11 : 16|8@1+ (1,0) [0|255] ""  PC
 SG_ M2P_SbmuPst_SysMinVolt_LvOn11 : 24|8@1+ (1,0) [0|255] ""  PC
 SG_ M2P_CscPst_SysMinVolt_LvOn11 : 32|8@1+ (1,0) [0|255] ""  PC
 SG_ M2P_CellPst_SysMinVolt_LvOn11 : 40|8@1+ (1,0) [0|255] ""  PC
 SG_ M2P_SbmuPst_SysMinTemp_LvOn11 : 48|8@1+ (1,0) [0|255] ""  PC
 SG_ M2P_CscPst_SysMinTemp_LvOn11 : 56|8@1+ (1,0) [0|255] ""  PC

BO_ 2332815004 M2P_SUMDATA11__12: 8 MBMU
 SG_ M2P_SbmuPst_SysMaxVolt_LvOn12 : 0|8@1+ (1,0) [0|255] ""  PC
 SG_ M2P_CscPst_SysMaxVolt_LvOn12 : 8|8@1+ (1,0) [0|255] ""  PC
 SG_ M2P_CellPst_SysMaxVolt_LvOn12 : 16|8@1+ (1,0) [0|255] ""  PC
 SG_ M2P_SbmuPst_SysMinVolt_LvOn12 : 24|8@1+ (1,0) [0|255] ""  PC
 SG_ M2P_CscPst_SysMinVolt_LvOn12 : 32|8@1+ (1,0) [0|255] ""  PC
 SG_ M2P_CellPst_SysMinVolt_LvOn12 : 40|8@1+ (1,0) [0|255] ""  PC
 SG_ M2P_SbmuPst_SysMinTemp_LvOn12 : 48|8@1+ (1,0) [0|255] ""  PC
 SG_ M2P_CscPst_SysMinTemp_LvOn12 : 56|8@1+ (1,0) [0|255] ""  PC

BO_ 2332815005 M2P_SUMDATA11__13: 8 MBMU
 SG_ M2P_SbmuPst_SysMaxVolt_LvOn13 : 0|8@1+ (1,0) [0|255] ""  PC
 SG_ M2P_CscPst_SysMaxVolt_LvOn13 : 8|8@1+ (1,0) [0|255] ""  PC
 SG_ M2P_CellPst_SysMaxVolt_LvOn13 : 16|8@1+ (1,0) [0|255] ""  PC
 SG_ M2P_SbmuPst_SysMinVolt_LvOn13 : 24|8@1+ (1,0) [0|255] ""  PC
 SG_ M2P_CscPst_SysMinVolt_LvOn13 : 32|8@1+ (1,0) [0|255] ""  PC
 SG_ M2P_CellPst_SysMinVolt_LvOn13 : 40|8@1+ (1,0) [0|255] ""  PC
 SG_ M2P_SbmuPst_SysMinTemp_LvOn13 : 48|8@1+ (1,0) [0|255] ""  PC
 SG_ M2P_CscPst_SysMinTemp_LvOn13 : 56|8@1+ (1,0) [0|255] ""  PC

BO_ 2332815006 M2P_SUMDATA11__14: 8 MBMU
 SG_ M2P_SbmuPst_SysMaxVolt_LvOn14 : 0|8@1+ (1,0) [0|255] ""  PC
 SG_ M2P_CscPst_SysMaxVolt_LvOn14 : 8|8@1+ (1,0) [0|255] ""  PC
 SG_ M2P_CellPst_SysMaxVolt_LvOn14 : 16|8@1+ (1,0) [0|255] ""  PC
 SG_ M2P_SbmuPst_SysMinVolt_LvOn14 : 24|8@1+ (1,0) [0|255] ""  PC
 SG_ M2P_CscPst_SysMinVolt_LvOn14 : 32|8@1+ (1,0) [0|255] ""  PC
 SG_ M2P_CellPst_SysMinVolt_LvOn14 : 40|8@1+ (1,0) [0|255] ""  PC
 SG_ M2P_SbmuPst_SysMinTemp_LvOn14 : 48|8@1+ (1,0) [0|255] ""  PC
 SG_ M2P_CscPst_SysMinTemp_LvOn14 : 56|8@1+ (1,0) [0|255] ""  PC

BO_ 2332815007 M2P_SUMDATA11__15: 8 MBMU
 SG_ M2P_SbmuPst_SysMaxVolt_LvOn15 : 0|8@1+ (1,0) [0|255] ""  PC
 SG_ M2P_CscPst_SysMaxVolt_LvOn15 : 8|8@1+ (1,0) [0|255] ""  PC
 SG_ M2P_CellPst_SysMaxVolt_LvOn15 : 16|8@1+ (1,0) [0|255] ""  PC
 SG_ M2P_SbmuPst_SysMinVolt_LvOn15 : 24|8@1+ (1,0) [0|255] ""  PC
 SG_ M2P_CscPst_SysMinVolt_LvOn15 : 32|8@1+ (1,0) [0|255] ""  PC
 SG_ M2P_CellPst_SysMinVolt_LvOn15 : 40|8@1+ (1,0) [0|255] ""  PC
 SG_ M2P_SbmuPst_SysMinTemp_LvOn15 : 48|8@1+ (1,0) [0|255] ""  PC
 SG_ M2P_CscPst_SysMinTemp_LvOn15 : 56|8@1+ (1,0) [0|255] ""  PC

BO_ 2332815008 M2P_SUMDATA11__16: 8 MBMU
 SG_ M2P_SbmuPst_SysMaxVolt_LvOn16 : 0|8@1+ (1,0) [0|255] ""  PC
 SG_ M2P_CscPst_SysMaxVolt_LvOn16 : 8|8@1+ (1,0) [0|255] ""  PC
 SG_ M2P_CellPst_SysMaxVolt_LvOn16 : 16|8@1+ (1,0) [0|255] ""  PC
 SG_ M2P_SbmuPst_SysMinVolt_LvOn16 : 24|8@1+ (1,0) [0|255] ""  PC
 SG_ M2P_CscPst_SysMinVolt_LvOn16 : 32|8@1+ (1,0) [0|255] ""  PC
 SG_ M2P_CellPst_SysMinVolt_LvOn16 : 40|8@1+ (1,0) [0|255] ""  PC
 SG_ M2P_SbmuPst_SysMinTemp_LvOn16 : 48|8@1+ (1,0) [0|255] ""  PC
 SG_ M2P_CscPst_SysMinTemp_LvOn16 : 56|8@1+ (1,0) [0|255] ""  PC

BO_ 2332815009 M2P_SUMDATA11__17: 8 MBMU
 SG_ M2P_SbmuPst_SysMaxVolt_LvOn17 : 0|8@1+ (1,0) [0|255] ""  PC
 SG_ M2P_CscPst_SysMaxVolt_LvOn17 : 8|8@1+ (1,0) [0|255] ""  PC
 SG_ M2P_CellPst_SysMaxVolt_LvOn17 : 16|8@1+ (1,0) [0|255] ""  PC
 SG_ M2P_SbmuPst_SysMinVolt_LvOn17 : 24|8@1+ (1,0) [0|255] ""  PC
 SG_ M2P_CscPst_SysMinVolt_LvOn17 : 32|8@1+ (1,0) [0|255] ""  PC
 SG_ M2P_CellPst_SysMinVolt_LvOn17 : 40|8@1+ (1,0) [0|255] ""  PC
 SG_ M2P_SbmuPst_SysMinTemp_LvOn17 : 48|8@1+ (1,0) [0|255] ""  PC
 SG_ M2P_CscPst_SysMinTemp_LvOn17 : 56|8@1+ (1,0) [0|255] ""  PC

BO_ 2332815010 M2P_SUMDATA11__18: 8 MBMU
 SG_ M2P_SbmuPst_SysMaxVolt_LvOn18 : 0|8@1+ (1,0) [0|255] ""  PC
 SG_ M2P_CscPst_SysMaxVolt_LvOn18 : 8|8@1+ (1,0) [0|255] ""  PC
 SG_ M2P_CellPst_SysMaxVolt_LvOn18 : 16|8@1+ (1,0) [0|255] ""  PC
 SG_ M2P_SbmuPst_SysMinVolt_LvOn18 : 24|8@1+ (1,0) [0|255] ""  PC
 SG_ M2P_CscPst_SysMinVolt_LvOn18 : 32|8@1+ (1,0) [0|255] ""  PC
 SG_ M2P_CellPst_SysMinVolt_LvOn18 : 40|8@1+ (1,0) [0|255] ""  PC
 SG_ M2P_SbmuPst_SysMinTemp_LvOn18 : 48|8@1+ (1,0) [0|255] ""  PC
 SG_ M2P_CscPst_SysMinTemp_LvOn18 : 56|8@1+ (1,0) [0|255] ""  PC

BO_ 2332815011 M2P_SUMDATA11__19: 8 MBMU
 SG_ M2P_SbmuPst_SysMaxVolt_LvOn19 : 0|8@1+ (1,0) [0|255] ""  PC
 SG_ M2P_CscPst_SysMaxVolt_LvOn19 : 8|8@1+ (1,0) [0|255] ""  PC
 SG_ M2P_CellPst_SysMaxVolt_LvOn19 : 16|8@1+ (1,0) [0|255] ""  PC
 SG_ M2P_SbmuPst_SysMinVolt_LvOn19 : 24|8@1+ (1,0) [0|255] ""  PC
 SG_ M2P_CscPst_SysMinVolt_LvOn19 : 32|8@1+ (1,0) [0|255] ""  PC
 SG_ M2P_CellPst_SysMinVolt_LvOn19 : 40|8@1+ (1,0) [0|255] ""  PC
 SG_ M2P_SbmuPst_SysMinTemp_LvOn19 : 48|8@1+ (1,0) [0|255] ""  PC
 SG_ M2P_CscPst_SysMinTemp_LvOn19 : 56|8@1+ (1,0) [0|255] ""  PC

BO_ 2332815012 M2P_SUMDATA11__20: 8 MBMU
 SG_ M2P_SbmuPst_SysMaxVolt_LvOn20 : 0|8@1+ (1,0) [0|255] ""  PC
 SG_ M2P_CscPst_SysMaxVolt_LvOn20 : 8|8@1+ (1,0) [0|255] ""  PC
 SG_ M2P_CellPst_SysMaxVolt_LvOn20 : 16|8@1+ (1,0) [0|255] ""  PC
 SG_ M2P_SbmuPst_SysMinVolt_LvOn20 : 24|8@1+ (1,0) [0|255] ""  PC
 SG_ M2P_CscPst_SysMinVolt_LvOn20 : 32|8@1+ (1,0) [0|255] ""  PC
 SG_ M2P_CellPst_SysMinVolt_LvOn20 : 40|8@1+ (1,0) [0|255] ""  PC
 SG_ M2P_SbmuPst_SysMinTemp_LvOn20 : 48|8@1+ (1,0) [0|255] ""  PC
 SG_ M2P_CscPst_SysMinTemp_LvOn20 : 56|8@1+ (1,0) [0|255] ""  PC

BO_ 2332815013 M2P_SUMDATA11__21: 8 MBMU
 SG_ M2P_SbmuPst_SysMaxVolt_LvOn21 : 0|8@1+ (1,0) [0|255] ""  PC
 SG_ M2P_CscPst_SysMaxVolt_LvOn21 : 8|8@1+ (1,0) [0|255] ""  PC
 SG_ M2P_CellPst_SysMaxVolt_LvOn21 : 16|8@1+ (1,0) [0|255] ""  PC
 SG_ M2P_SbmuPst_SysMinVolt_LvOn21 : 24|8@1+ (1,0) [0|255] ""  PC
 SG_ M2P_CscPst_SysMinVolt_LvOn21 : 32|8@1+ (1,0) [0|255] ""  PC
 SG_ M2P_CellPst_SysMinVolt_LvOn21 : 40|8@1+ (1,0) [0|255] ""  PC
 SG_ M2P_SbmuPst_SysMinTemp_LvOn21 : 48|8@1+ (1,0) [0|255] ""  PC
 SG_ M2P_CscPst_SysMinTemp_LvOn21 : 56|8@1+ (1,0) [0|255] ""  PC

BO_ 2332815014 M2P_SUMDATA11__22: 8 MBMU
 SG_ M2P_SbmuPst_SysMaxVolt_LvOn22 : 0|8@1+ (1,0) [0|255] ""  PC
 SG_ M2P_CscPst_SysMaxVolt_LvOn22 : 8|8@1+ (1,0) [0|255] ""  PC
 SG_ M2P_CellPst_SysMaxVolt_LvOn22 : 16|8@1+ (1,0) [0|255] ""  PC
 SG_ M2P_SbmuPst_SysMinVolt_LvOn22 : 24|8@1+ (1,0) [0|255] ""  PC
 SG_ M2P_CscPst_SysMinVolt_LvOn22 : 32|8@1+ (1,0) [0|255] ""  PC
 SG_ M2P_CellPst_SysMinVolt_LvOn22 : 40|8@1+ (1,0) [0|255] ""  PC
 SG_ M2P_SbmuPst_SysMinTemp_LvOn22 : 48|8@1+ (1,0) [0|255] ""  PC
 SG_ M2P_CscPst_SysMinTemp_LvOn22 : 56|8@1+ (1,0) [0|255] ""  PC

BO_ 2332815015 M2P_SUMDATA11__23: 8 MBMU
 SG_ M2P_SbmuPst_SysMaxVolt_LvOn23 : 0|8@1+ (1,0) [0|255] ""  PC
 SG_ M2P_CscPst_SysMaxVolt_LvOn23 : 8|8@1+ (1,0) [0|255] ""  PC
 SG_ M2P_CellPst_SysMaxVolt_LvOn23 : 16|8@1+ (1,0) [0|255] ""  PC
 SG_ M2P_SbmuPst_SysMinVolt_LvOn23 : 24|8@1+ (1,0) [0|255] ""  PC
 SG_ M2P_CscPst_SysMinVolt_LvOn23 : 32|8@1+ (1,0) [0|255] ""  PC
 SG_ M2P_CellPst_SysMinVolt_LvOn23 : 40|8@1+ (1,0) [0|255] ""  PC
 SG_ M2P_SbmuPst_SysMinTemp_LvOn23 : 48|8@1+ (1,0) [0|255] ""  PC
 SG_ M2P_CscPst_SysMinTemp_LvOn23 : 56|8@1+ (1,0) [0|255] ""  PC

BO_ 2332815016 M2P_SUMDATA11__24: 8 MBMU
 SG_ M2P_SbmuPst_SysMaxVolt_LvOn24 : 0|8@1+ (1,0) [0|255] ""  PC
 SG_ M2P_CscPst_SysMaxVolt_LvOn24 : 8|8@1+ (1,0) [0|255] ""  PC
 SG_ M2P_CellPst_SysMaxVolt_LvOn24 : 16|8@1+ (1,0) [0|255] ""  PC
 SG_ M2P_SbmuPst_SysMinVolt_LvOn24 : 24|8@1+ (1,0) [0|255] ""  PC
 SG_ M2P_CscPst_SysMinVolt_LvOn24 : 32|8@1+ (1,0) [0|255] ""  PC
 SG_ M2P_CellPst_SysMinVolt_LvOn24 : 40|8@1+ (1,0) [0|255] ""  PC
 SG_ M2P_SbmuPst_SysMinTemp_LvOn24 : 48|8@1+ (1,0) [0|255] ""  PC
 SG_ M2P_CscPst_SysMinTemp_LvOn24 : 56|8@1+ (1,0) [0|255] ""  PC

BO_ 2332815017 M2P_SUMDATA11__25: 8 MBMU
 SG_ M2P_SbmuPst_SysMaxVolt_LvOn25 : 0|8@1+ (1,0) [0|255] ""  PC
 SG_ M2P_CscPst_SysMaxVolt_LvOn25 : 8|8@1+ (1,0) [0|255] ""  PC
 SG_ M2P_CellPst_SysMaxVolt_LvOn25 : 16|8@1+ (1,0) [0|255] ""  PC
 SG_ M2P_SbmuPst_SysMinVolt_LvOn25 : 24|8@1+ (1,0) [0|255] ""  PC
 SG_ M2P_CscPst_SysMinVolt_LvOn25 : 32|8@1+ (1,0) [0|255] ""  PC
 SG_ M2P_CellPst_SysMinVolt_LvOn25 : 40|8@1+ (1,0) [0|255] ""  PC
 SG_ M2P_SbmuPst_SysMinTemp_LvOn25 : 48|8@1+ (1,0) [0|255] ""  PC
 SG_ M2P_CscPst_SysMinTemp_LvOn25 : 56|8@1+ (1,0) [0|255] ""  PC

BO_ 2332815018 M2P_SUMDATA11__26: 8 MBMU
 SG_ M2P_SbmuPst_SysMaxVolt_LvOn26 : 0|8@1+ (1,0) [0|255] ""  PC
 SG_ M2P_CscPst_SysMaxVolt_LvOn26 : 8|8@1+ (1,0) [0|255] ""  PC
 SG_ M2P_CellPst_SysMaxVolt_LvOn26 : 16|8@1+ (1,0) [0|255] ""  PC
 SG_ M2P_SbmuPst_SysMinVolt_LvOn26 : 24|8@1+ (1,0) [0|255] ""  PC
 SG_ M2P_CscPst_SysMinVolt_LvOn26 : 32|8@1+ (1,0) [0|255] ""  PC
 SG_ M2P_CellPst_SysMinVolt_LvOn26 : 40|8@1+ (1,0) [0|255] ""  PC
 SG_ M2P_SbmuPst_SysMinTemp_LvOn26 : 48|8@1+ (1,0) [0|255] ""  PC
 SG_ M2P_CscPst_SysMinTemp_LvOn26 : 56|8@1+ (1,0) [0|255] ""  PC

BO_ 2332815019 M2P_SUMDATA11__27: 8 MBMU
 SG_ M2P_SbmuPst_SysMaxVolt_LvOn27 : 0|8@1+ (1,0) [0|255] ""  PC
 SG_ M2P_CscPst_SysMaxVolt_LvOn27 : 8|8@1+ (1,0) [0|255] ""  PC
 SG_ M2P_CellPst_SysMaxVolt_LvOn27 : 16|8@1+ (1,0) [0|255] ""  PC
 SG_ M2P_SbmuPst_SysMinVolt_LvOn27 : 24|8@1+ (1,0) [0|255] ""  PC
 SG_ M2P_CscPst_SysMinVolt_LvOn27 : 32|8@1+ (1,0) [0|255] ""  PC
 SG_ M2P_CellPst_SysMinVolt_LvOn27 : 40|8@1+ (1,0) [0|255] ""  PC
 SG_ M2P_SbmuPst_SysMinTemp_LvOn27 : 48|8@1+ (1,0) [0|255] ""  PC
 SG_ M2P_CscPst_SysMinTemp_LvOn27 : 56|8@1+ (1,0) [0|255] ""  PC

BO_ 2332815020 M2P_SUMDATA11__28: 8 MBMU
 SG_ M2P_SbmuPst_SysMaxVolt_LvOn28 : 0|8@1+ (1,0) [0|255] ""  PC
 SG_ M2P_CscPst_SysMaxVolt_LvOn28 : 8|8@1+ (1,0) [0|255] ""  PC
 SG_ M2P_CellPst_SysMaxVolt_LvOn28 : 16|8@1+ (1,0) [0|255] ""  PC
 SG_ M2P_SbmuPst_SysMinVolt_LvOn28 : 24|8@1+ (1,0) [0|255] ""  PC
 SG_ M2P_CscPst_SysMinVolt_LvOn28 : 32|8@1+ (1,0) [0|255] ""  PC
 SG_ M2P_CellPst_SysMinVolt_LvOn28 : 40|8@1+ (1,0) [0|255] ""  PC
 SG_ M2P_SbmuPst_SysMinTemp_LvOn28 : 48|8@1+ (1,0) [0|255] ""  PC
 SG_ M2P_CscPst_SysMinTemp_LvOn28 : 56|8@1+ (1,0) [0|255] ""  PC

BO_ 2332815021 M2P_SUMDATA11__29: 8 MBMU
 SG_ M2P_SbmuPst_SysMaxVolt_LvOn29 : 0|8@1+ (1,0) [0|255] ""  PC
 SG_ M2P_CscPst_SysMaxVolt_LvOn29 : 8|8@1+ (1,0) [0|255] ""  PC
 SG_ M2P_CellPst_SysMaxVolt_LvOn29 : 16|8@1+ (1,0) [0|255] ""  PC
 SG_ M2P_SbmuPst_SysMinVolt_LvOn29 : 24|8@1+ (1,0) [0|255] ""  PC
 SG_ M2P_CscPst_SysMinVolt_LvOn29 : 32|8@1+ (1,0) [0|255] ""  PC
 SG_ M2P_CellPst_SysMinVolt_LvOn29 : 40|8@1+ (1,0) [0|255] ""  PC
 SG_ M2P_SbmuPst_SysMinTemp_LvOn29 : 48|8@1+ (1,0) [0|255] ""  PC
 SG_ M2P_CscPst_SysMinTemp_LvOn29 : 56|8@1+ (1,0) [0|255] ""  PC

BO_ 2332815022 M2P_SUMDATA11__30: 8 MBMU
 SG_ M2P_SbmuPst_SysMaxVolt_LvOn30 : 0|8@1+ (1,0) [0|255] ""  PC
 SG_ M2P_CscPst_SysMaxVolt_LvOn30 : 8|8@1+ (1,0) [0|255] ""  PC
 SG_ M2P_CellPst_SysMaxVolt_LvOn30 : 16|8@1+ (1,0) [0|255] ""  PC
 SG_ M2P_SbmuPst_SysMinVolt_LvOn30 : 24|8@1+ (1,0) [0|255] ""  PC
 SG_ M2P_CscPst_SysMinVolt_LvOn30 : 32|8@1+ (1,0) [0|255] ""  PC
 SG_ M2P_CellPst_SysMinVolt_LvOn30 : 40|8@1+ (1,0) [0|255] ""  PC
 SG_ M2P_SbmuPst_SysMinTemp_LvOn30 : 48|8@1+ (1,0) [0|255] ""  PC
 SG_ M2P_CscPst_SysMinTemp_LvOn30 : 56|8@1+ (1,0) [0|255] ""  PC

BO_ 2332815023 M2P_SUMDATA11__31: 8 MBMU
 SG_ M2P_SbmuPst_SysMaxVolt_LvOn31 : 0|8@1+ (1,0) [0|255] ""  PC
 SG_ M2P_CscPst_SysMaxVolt_LvOn31 : 8|8@1+ (1,0) [0|255] ""  PC
 SG_ M2P_CellPst_SysMaxVolt_LvOn31 : 16|8@1+ (1,0) [0|255] ""  PC
 SG_ M2P_SbmuPst_SysMinVolt_LvOn31 : 24|8@1+ (1,0) [0|255] ""  PC
 SG_ M2P_CscPst_SysMinVolt_LvOn31 : 32|8@1+ (1,0) [0|255] ""  PC
 SG_ M2P_CellPst_SysMinVolt_LvOn31 : 40|8@1+ (1,0) [0|255] ""  PC
 SG_ M2P_SbmuPst_SysMinTemp_LvOn31 : 48|8@1+ (1,0) [0|255] ""  PC
 SG_ M2P_CscPst_SysMinTemp_LvOn31 : 56|8@1+ (1,0) [0|255] ""  PC

BO_ 2165538798 P2S_CMD2: 8 PC
 SG_ P2S_CMD2_data0 : 0|8@1+ (1,0) [0|255] ""  SBMU
 SG_ P2S_CMD2_data1 : 8|8@1+ (1,0) [0|255] ""  SBMU
 SG_ P2S_CMD2_data2 : 16|8@1+ (1,0) [0|255] ""  SBMU
 SG_ P2S_CMD2_data3 : 24|8@1+ (1,0) [0|255] ""  SBMU
 SG_ P2S_CMD2_data4 : 32|8@1+ (1,0) [0|255] ""  SBMU
 SG_ P2S_CMD2_data5 : 40|8@1+ (1,0) [0|255] ""  SBMU
 SG_ P2S_CMD2_data6 : 48|8@1+ (1,0) [0|255] ""  SBMU
 SG_ P2S_CMD2_data7 : 56|8@1+ (1,0) [0|255] ""  SBMU

BO_ 2149100270 P2M_CMD6: 8 PC
 SG_ P2M_CMD6_data0 : 0|8@1+ (1,0) [0|255] ""  SBMU
 SG_ P2M_CMD6_data1 : 8|8@1+ (1,0) [0|255] ""  MBMU
 SG_ P2M_CMD6_data2 : 16|8@1+ (1,0) [0|255] ""  MBMU
 SG_ P2M_CMD6_data3 : 24|8@1+ (1,0) [0|255] ""  MBMU
 SG_ P2M_CMD6_data4 : 32|8@1+ (1,0) [0|255] ""  MBMU
 SG_ P2M_CMD6_data5 : 40|8@1+ (1,0) [0|255] ""  MBMU
 SG_ P2M_CMD6_data6 : 48|8@1+ (1,0) [0|255] ""  MBMU
 SG_ P2M_CMD6_data7 : 56|8@1+ (1,0) [0|255] ""  MBMU

BO_ 2333736769 S2A_SUMDATA19__01: 8 SBMU
 SG_ S2A_HisOTtimes_01 : 0|16@1+ (1,0) [0|65535] "s"  MBMU
 SG_ S2A_ChgtimeatLowtemp_01 : 16|32@1+ (1,0) [0|4294967295] "s"  MBMU

BO_ 2333736770 S2A_SUMDATA19__02: 8 SBMU
 SG_ S2A_HisOTtimes_02 : 0|16@1+ (1,0) [0|65535] "s"  MBMU
 SG_ S2A_ChgtimeatLowtemp_02 : 16|32@1+ (1,0) [0|4294967295] "s"  MBMU

BO_ 2333736771 S2A_SUMDATA19__03: 8 SBMU
 SG_ S2A_HisOTtimes_03 : 0|16@1+ (1,0) [0|65535] "s"  MBMU
 SG_ S2A_ChgtimeatLowtemp_03 : 16|32@1+ (1,0) [0|4294967295] "s"  MBMU

BO_ 2333736772 S2A_SUMDATA19__04: 8 SBMU
 SG_ S2A_HisOTtimes_04 : 0|16@1+ (1,0) [0|65535] "s"  MBMU
 SG_ S2A_ChgtimeatLowtemp_04 : 16|32@1+ (1,0) [0|4294967295] "s"  MBMU

BO_ 2333736773 S2A_SUMDATA19__05: 8 SBMU
 SG_ S2A_HisOTtimes_05 : 0|16@1+ (1,0) [0|65535] "s"  MBMU
 SG_ S2A_ChgtimeatLowtemp_05 : 16|32@1+ (1,0) [0|4294967295] "s"  MBMU

BO_ 2333736774 S2A_SUMDATA19__06: 8 SBMU
 SG_ S2A_HisOTtimes_06 : 0|16@1+ (1,0) [0|65535] "s"  MBMU
 SG_ S2A_ChgtimeatLowtemp_06 : 16|32@1+ (1,0) [0|4294967295] "s"  MBMU

BO_ 2333736775 S2A_SUMDATA19__07: 8 SBMU
 SG_ S2A_HisOTtimes_07 : 0|16@1+ (1,0) [0|65535] "s"  MBMU
 SG_ S2A_ChgtimeatLowtemp_07 : 16|32@1+ (1,0) [0|4294967295] "s"  MBMU

BO_ 2333736776 S2A_SUMDATA19__08: 8 SBMU
 SG_ S2A_HisOTtimes_08 : 0|16@1+ (1,0) [0|65535] "s"  MBMU
 SG_ S2A_ChgtimeatLowtemp_08 : 16|32@1+ (1,0) [0|4294967295] "s"  MBMU

BO_ 2333736777 S2A_SUMDATA19__09: 8 SBMU
 SG_ S2A_HisOTtimes_09 : 0|16@1+ (1,0) [0|65535] "s"  MBMU
 SG_ S2A_ChgtimeatLowtemp_09 : 16|32@1+ (1,0) [0|4294967295] "s"  MBMU

BO_ 2333736778 S2A_SUMDATA19__10: 8 SBMU
 SG_ S2A_HisOTtimes_10 : 0|16@1+ (1,0) [0|65535] "s"  MBMU
 SG_ S2A_ChgtimeatLowtemp_10 : 16|32@1+ (1,0) [0|4294967295] "s"  MBMU

BO_ 2333736779 S2A_SUMDATA19__11: 8 SBMU
 SG_ S2A_HisOTtimes_11 : 0|16@1+ (1,0) [0|65535] "s"  MBMU
 SG_ S2A_ChgtimeatLowtemp_11 : 16|32@1+ (1,0) [0|4294967295] "s"  MBMU

BO_ 2333736780 S2A_SUMDATA19__12: 8 SBMU
 SG_ S2A_HisOTtimes_12 : 0|16@1+ (1,0) [0|65535] "s"  MBMU
 SG_ S2A_ChgtimeatLowtemp_12 : 16|32@1+ (1,0) [0|4294967295] "s"  MBMU

BO_ 2333736781 S2A_SUMDATA19__13: 8 SBMU
 SG_ S2A_HisOTtimes_13 : 0|16@1+ (1,0) [0|65535] "s"  MBMU
 SG_ S2A_ChgtimeatLowtemp_13 : 16|32@1+ (1,0) [0|4294967295] "s"  MBMU

BO_ 2333736782 S2A_SUMDATA19__14: 8 SBMU
 SG_ S2A_HisOTtimes_14 : 0|16@1+ (1,0) [0|65535] "s"  MBMU
 SG_ S2A_ChgtimeatLowtemp_14 : 16|32@1+ (1,0) [0|4294967295] "s"  MBMU

BO_ 2333736783 S2A_SUMDATA19__15: 8 SBMU
 SG_ S2A_HisOTtimes_15 : 0|16@1+ (1,0) [0|65535] "s"  MBMU
 SG_ S2A_ChgtimeatLowtemp_15 : 16|32@1+ (1,0) [0|4294967295] "s"  MBMU

BO_ 2333736784 S2A_SUMDATA19__16: 8 SBMU
 SG_ S2A_HisOTtimes_16 : 0|16@1+ (1,0) [0|65535] "s"  MBMU
 SG_ S2A_ChgtimeatLowtemp_16 : 16|32@1+ (1,0) [0|4294967295] "s"  MBMU

BO_ 2333736785 S2A_SUMDATA19__17: 8 SBMU
 SG_ S2A_HisOTtimes_17 : 0|16@1+ (1,0) [0|65535] "s"  MBMU
 SG_ S2A_ChgtimeatLowtemp_17 : 16|32@1+ (1,0) [0|4294967295] "s"  MBMU

BO_ 2333736786 S2A_SUMDATA19__18: 8 SBMU
 SG_ S2A_HisOTtimes_18 : 0|16@1+ (1,0) [0|65535] "s"  MBMU
 SG_ S2A_ChgtimeatLowtemp_18 : 16|32@1+ (1,0) [0|4294967295] "s"  MBMU

BO_ 2333736787 S2A_SUMDATA19__19: 8 SBMU
 SG_ S2A_HisOTtimes_19 : 0|16@1+ (1,0) [0|65535] "s"  MBMU
 SG_ S2A_ChgtimeatLowtemp_19 : 16|32@1+ (1,0) [0|4294967295] "s"  MBMU

BO_ 2333736788 S2A_SUMDATA19__20: 8 SBMU
 SG_ S2A_HisOTtimes_20 : 0|16@1+ (1,0) [0|65535] "s"  MBMU
 SG_ S2A_ChgtimeatLowtemp_20 : 16|32@1+ (1,0) [0|4294967295] "s"  MBMU

BO_ 2333736789 S2A_SUMDATA19__21: 8 SBMU
 SG_ S2A_HisOTtimes_21 : 0|16@1+ (1,0) [0|65535] "s"  MBMU
 SG_ S2A_ChgtimeatLowtemp_21 : 16|32@1+ (1,0) [0|4294967295] "s"  MBMU

BO_ 2333736790 S2A_SUMDATA19__22: 8 SBMU
 SG_ S2A_HisOTtimes_22 : 0|16@1+ (1,0) [0|65535] "s"  MBMU
 SG_ S2A_ChgtimeatLowtemp_22 : 16|32@1+ (1,0) [0|4294967295] "s"  MBMU

BO_ 2333736791 S2A_SUMDATA19__23: 8 SBMU
 SG_ S2A_HisOTtimes_23 : 0|16@1+ (1,0) [0|65535] "s"  MBMU
 SG_ S2A_ChgtimeatLowtemp_23 : 16|32@1+ (1,0) [0|4294967295] "s"  MBMU

BO_ 2333736792 S2A_SUMDATA19__24: 8 SBMU
 SG_ S2A_HisOTtimes_24 : 0|16@1+ (1,0) [0|65535] "s"  MBMU
 SG_ S2A_ChgtimeatLowtemp_24 : 16|32@1+ (1,0) [0|4294967295] "s"  MBMU

BO_ 2333736793 S2A_SUMDATA19__25: 8 SBMU
 SG_ S2A_HisOTtimes_25 : 0|16@1+ (1,0) [0|65535] "s"  MBMU
 SG_ S2A_ChgtimeatLowtemp_25 : 16|32@1+ (1,0) [0|4294967295] "s"  MBMU

BO_ 2333736794 S2A_SUMDATA19__26: 8 SBMU
 SG_ S2A_HisOTtimes_26 : 0|16@1+ (1,0) [0|65535] "s"  MBMU
 SG_ S2A_ChgtimeatLowtemp_26 : 16|32@1+ (1,0) [0|4294967295] "s"  MBMU

BO_ 2333736795 S2A_SUMDATA19__27: 8 SBMU
 SG_ S2A_HisOTtimes_27 : 0|16@1+ (1,0) [0|65535] "s"  MBMU
 SG_ S2A_ChgtimeatLowtemp_27 : 16|32@1+ (1,0) [0|4294967295] "s"  MBMU

BO_ 2333736796 S2A_SUMDATA19__28: 8 SBMU
 SG_ S2A_HisOTtimes_28 : 0|16@1+ (1,0) [0|65535] "s"  MBMU
 SG_ S2A_ChgtimeatLowtemp_28 : 16|32@1+ (1,0) [0|4294967295] "s"  MBMU

BO_ 2333736797 S2A_SUMDATA19__29: 8 SBMU
 SG_ S2A_HisOTtimes_29 : 0|16@1+ (1,0) [0|65535] "s"  MBMU
 SG_ S2A_ChgtimeatLowtemp_29 : 16|32@1+ (1,0) [0|4294967295] "s"  MBMU

BO_ 2333736798 S2A_SUMDATA19__30: 8 SBMU
 SG_ S2A_HisOTtimes_30 : 0|16@1+ (1,0) [0|65535] "s"  MBMU
 SG_ S2A_ChgtimeatLowtemp_30 : 16|32@1+ (1,0) [0|4294967295] "s"  MBMU

BO_ 2333736799 S2A_SUMDATA19__31: 8 SBMU
 SG_ S2A_HisOTtimes_31 : 0|16@1+ (1,0) [0|65535] "s"  MBMU
 SG_ S2A_ChgtimeatLowtemp_31 : 16|32@1+ (1,0) [0|4294967295] "s"  MBMU

BO_ 2333736800 S2A_SUMDATA19__32: 8 SBMU
 SG_ S2A_HisOTtimes_32 : 0|16@1+ (1,0) [0|65535] "s"  MBMU
 SG_ S2A_ChgtimeatLowtemp_32 : 16|32@1+ (1,0) [0|4294967295] "s"  MBMU

BO_ 2333736801 S2A_SUMDATA19__33: 8 SBMU
 SG_ S2A_HisOTtimes_33 : 0|16@1+ (1,0) [0|65535] "s"  MBMU
 SG_ S2A_ChgtimeatLowtemp_33 : 16|32@1+ (1,0) [0|4294967295] "s"  MBMU

BO_ 2333736802 S2A_SUMDATA19__34: 8 SBMU
 SG_ S2A_HisOTtimes_34 : 0|16@1+ (1,0) [0|65535] "s"  MBMU
 SG_ S2A_ChgtimeatLowtemp_34 : 16|32@1+ (1,0) [0|4294967295] "s"  MBMU

BO_ 2333736803 S2A_SUMDATA19__35: 8 SBMU
 SG_ S2A_HisOTtimes_35 : 0|16@1+ (1,0) [0|65535] "s"  MBMU
 SG_ S2A_ChgtimeatLowtemp_35 : 16|32@1+ (1,0) [0|4294967295] "s"  MBMU

BO_ 2333736804 S2A_SUMDATA19__36: 8 SBMU
 SG_ S2A_HisOTtimes_36 : 0|16@1+ (1,0) [0|65535] "s"  MBMU
 SG_ S2A_ChgtimeatLowtemp_36 : 16|32@1+ (1,0) [0|4294967295] "s"  MBMU

BO_ 2333736805 S2A_SUMDATA19__37: 8 SBMU
 SG_ S2A_HisOTtimes_37 : 0|16@1+ (1,0) [0|65535] "s"  MBMU
 SG_ S2A_ChgtimeatLowtemp_37 : 16|32@1+ (1,0) [0|4294967295] "s"  MBMU

BO_ 2333736806 S2A_SUMDATA19__38: 8 SBMU
 SG_ S2A_HisOTtimes_38 : 0|16@1+ (1,0) [0|65535] "s"  MBMU
 SG_ S2A_ChgtimeatLowtemp_38 : 16|32@1+ (1,0) [0|4294967295] "s"  MBMU

BO_ 2333736807 S2A_SUMDATA19__39: 8 SBMU
 SG_ S2A_HisOTtimes_39 : 0|16@1+ (1,0) [0|65535] "s"  MBMU
 SG_ S2A_ChgtimeatLowtemp_39 : 16|32@1+ (1,0) [0|4294967295] "s"  MBMU

BO_ 2333736808 S2A_SUMDATA19__40: 8 SBMU
 SG_ S2A_HisOTtimes_40 : 0|16@1+ (1,0) [0|65535] "s"  MBMU
 SG_ S2A_ChgtimeatLowtemp_40 : 16|32@1+ (1,0) [0|4294967295] "s"  MBMU

BO_ 2333736809 S2A_SUMDATA19__41: 8 SBMU
 SG_ S2A_HisOTtimes_41 : 0|16@1+ (1,0) [0|65535] "s"  MBMU
 SG_ S2A_ChgtimeatLowtemp_41 : 16|32@1+ (1,0) [0|4294967295] "s"  MBMU

BO_ 2333736810 S2A_SUMDATA19__42: 8 SBMU
 SG_ S2A_HisOTtimes_42 : 0|16@1+ (1,0) [0|65535] "s"  MBMU
 SG_ S2A_ChgtimeatLowtemp_42 : 16|32@1+ (1,0) [0|4294967295] "s"  MBMU

BO_ 2333736811 S2A_SUMDATA19__43: 8 SBMU
 SG_ S2A_HisOTtimes_43 : 0|16@1+ (1,0) [0|65535] "s"  MBMU
 SG_ S2A_ChgtimeatLowtemp_43 : 16|32@1+ (1,0) [0|4294967295] "s"  MBMU

BO_ 2333736812 S2A_SUMDATA19__44: 8 SBMU
 SG_ S2A_HisOTtimes_44 : 0|16@1+ (1,0) [0|65535] "s"  MBMU
 SG_ S2A_ChgtimeatLowtemp_44 : 16|32@1+ (1,0) [0|4294967295] "s"  MBMU

BO_ 2333736813 S2A_SUMDATA19__45: 8 SBMU
 SG_ S2A_HisOTtimes_45 : 0|16@1+ (1,0) [0|65535] "s"  MBMU
 SG_ S2A_ChgtimeatLowtemp_45 : 16|32@1+ (1,0) [0|4294967295] "s"  MBMU

BO_ 2333736814 S2A_SUMDATA19__46: 8 SBMU
 SG_ S2A_HisOTtimes_46 : 0|16@1+ (1,0) [0|65535] "s"  MBMU
 SG_ S2A_ChgtimeatLowtemp_46 : 16|32@1+ (1,0) [0|4294967295] "s"  MBMU

BO_ 2333736815 S2A_SUMDATA19__47: 8 SBMU
 SG_ S2A_HisOTtimes_47 : 0|16@1+ (1,0) [0|65535] "s"  MBMU
 SG_ S2A_ChgtimeatLowtemp_47 : 16|32@1+ (1,0) [0|4294967295] "s"  MBMU

BO_ 2333736816 S2A_SUMDATA19__48: 8 SBMU
 SG_ S2A_HisOTtimes_48 : 0|16@1+ (1,0) [0|65535] "s"  MBMU
 SG_ S2A_ChgtimeatLowtemp_48 : 16|32@1+ (1,0) [0|4294967295] "s"  MBMU

BO_ 2333736817 S2A_SUMDATA19__49: 8 SBMU
 SG_ S2A_HisOTtimes_49 : 0|16@1+ (1,0) [0|65535] "s"  MBMU
 SG_ S2A_ChgtimeatLowtemp_49 : 16|32@1+ (1,0) [0|4294967295] "s"  MBMU

BO_ 2333736818 S2A_SUMDATA19__50: 8 SBMU
 SG_ S2A_HisOTtimes_50 : 0|16@1+ (1,0) [0|65535] "s"  MBMU
 SG_ S2A_ChgtimeatLowtemp_50 : 16|32@1+ (1,0) [0|4294967295] "s"  MBMU

BO_ 2333736819 S2A_SUMDATA19__51: 8 SBMU
 SG_ S2A_HisOTtimes_51 : 0|16@1+ (1,0) [0|65535] "s"  MBMU
 SG_ S2A_ChgtimeatLowtemp_51 : 16|32@1+ (1,0) [0|4294967295] "s"  MBMU

BO_ 2333736820 S2A_SUMDATA19__52: 8 SBMU
 SG_ S2A_HisOTtimes_52 : 0|16@1+ (1,0) [0|65535] "s"  MBMU
 SG_ S2A_ChgtimeatLowtemp_52 : 16|32@1+ (1,0) [0|4294967295] "s"  MBMU

BO_ 2333736821 S2A_SUMDATA19__53: 8 SBMU
 SG_ S2A_HisOTtimes_53 : 0|16@1+ (1,0) [0|65535] "s"  MBMU
 SG_ S2A_ChgtimeatLowtemp_53 : 16|32@1+ (1,0) [0|4294967295] "s"  MBMU

BO_ 2333736822 S2A_SUMDATA19__54: 8 SBMU
 SG_ S2A_HisOTtimes_54 : 0|16@1+ (1,0) [0|65535] "s"  MBMU
 SG_ S2A_ChgtimeatLowtemp_54 : 16|32@1+ (1,0) [0|4294967295] "s"  MBMU

BO_ 2333736823 S2A_SUMDATA19__55: 8 SBMU
 SG_ S2A_HisOTtimes_55 : 0|16@1+ (1,0) [0|65535] "s"  MBMU
 SG_ S2A_ChgtimeatLowtemp_55 : 16|32@1+ (1,0) [0|4294967295] "s"  MBMU

BO_ 2333736824 S2A_SUMDATA19__56: 8 SBMU
 SG_ S2A_HisOTtimes_56 : 0|16@1+ (1,0) [0|65535] "s"  MBMU
 SG_ S2A_ChgtimeatLowtemp_56 : 16|32@1+ (1,0) [0|4294967295] "s"  MBMU

BO_ 2333736825 S2A_SUMDATA19__57: 8 SBMU
 SG_ S2A_HisOTtimes_57 : 0|16@1+ (1,0) [0|65535] "s"  MBMU
 SG_ S2A_ChgtimeatLowtemp_57 : 16|32@1+ (1,0) [0|4294967295] "s"  MBMU

BO_ 2333736826 S2A_SUMDATA19__58: 8 SBMU
 SG_ S2A_HisOTtimes_58 : 0|16@1+ (1,0) [0|65535] "s"  MBMU
 SG_ S2A_ChgtimeatLowtemp_58 : 16|32@1+ (1,0) [0|4294967295] "s"  MBMU

BO_ 2333736827 S2A_SUMDATA19__59: 8 SBMU
 SG_ S2A_HisOTtimes_59 : 0|16@1+ (1,0) [0|65535] "s"  MBMU
 SG_ S2A_ChgtimeatLowtemp_59 : 16|32@1+ (1,0) [0|4294967295] "s"  MBMU

BO_ 2333736828 S2A_SUMDATA19__60: 8 SBMU
 SG_ S2A_HisOTtimes_60 : 0|16@1+ (1,0) [0|65535] "s"  MBMU
 SG_ S2A_ChgtimeatLowtemp_60 : 16|32@1+ (1,0) [0|4294967295] "s"  MBMU

BO_ 2333736829 S2A_SUMDATA19__61: 8 SBMU
 SG_ S2A_HisOTtimes_61 : 0|16@1+ (1,0) [0|65535] "s"  MBMU
 SG_ S2A_ChgtimeatLowtemp_61 : 16|32@1+ (1,0) [0|4294967295] "s"  MBMU

BO_ 2333736830 S2A_SUMDATA19__62: 8 SBMU
 SG_ S2A_HisOTtimes_62 : 0|16@1+ (1,0) [0|65535] "s"  MBMU
 SG_ S2A_ChgtimeatLowtemp_62 : 16|32@1+ (1,0) [0|4294967295] "s"  MBMU

BO_ 2333736831 S2A_SUMDATA19__63: 8 SBMU
 SG_ S2A_HisOTtimes_63 : 0|16@1+ (1,0) [0|65535] "s"  MBMU
 SG_ S2A_ChgtimeatLowtemp_63 : 16|32@1+ (1,0) [0|4294967295] "s"  MBMU

BO_ 2334195521 S2A_SUMDATA20__01: 8 SBMU
 SG_ S2A_DurationatLowtemp_01 : 0|32@1+ (1,0) [0|4294967295] "s"  MBMU
 SG_ S2A_DurationatHightemp_01 : 32|32@1+ (1,0) [0|4294967295] "s"  MBMU

BO_ 2334195522 S2A_SUMDATA20__02: 8 SBMU
 SG_ S2A_DurationatLowtemp_02 : 0|32@1+ (1,0) [0|4294967295] "s"  MBMU
 SG_ S2A_DurationatHightemp_02 : 32|32@1+ (1,0) [0|4294967295] "s"  MBMU

BO_ 2334195523 S2A_SUMDATA20__03: 8 SBMU
 SG_ S2A_DurationatLowtemp_03 : 0|32@1+ (1,0) [0|4294967295] "s"  MBMU
 SG_ S2A_DurationatHightemp_03 : 32|32@1+ (1,0) [0|4294967295] "s"  MBMU

BO_ 2334195524 S2A_SUMDATA20__04: 8 SBMU
 SG_ S2A_DurationatLowtemp_04 : 0|32@1+ (1,0) [0|4294967295] "s"  MBMU
 SG_ S2A_DurationatHightemp_04 : 32|32@1+ (1,0) [0|4294967295] "s"  MBMU

BO_ 2334195525 S2A_SUMDATA20__05: 8 SBMU
 SG_ S2A_DurationatLowtemp_05 : 0|32@1+ (1,0) [0|4294967295] "s"  MBMU
 SG_ S2A_DurationatHightemp_05 : 32|32@1+ (1,0) [0|4294967295] "s"  MBMU

BO_ 2334195526 S2A_SUMDATA20__06: 8 SBMU
 SG_ S2A_DurationatLowtemp_06 : 0|32@1+ (1,0) [0|4294967295] "s"  MBMU
 SG_ S2A_DurationatHightemp_06 : 32|32@1+ (1,0) [0|4294967295] "s"  MBMU

BO_ 2334195527 S2A_SUMDATA20__07: 8 SBMU
 SG_ S2A_DurationatLowtemp_07 : 0|32@1+ (1,0) [0|4294967295] "s"  MBMU
 SG_ S2A_DurationatHightemp_07 : 32|32@1+ (1,0) [0|4294967295] "s"  MBMU

BO_ 2334195528 S2A_SUMDATA20__08: 8 SBMU
 SG_ S2A_DurationatLowtemp_08 : 0|32@1+ (1,0) [0|4294967295] "s"  MBMU
 SG_ S2A_DurationatHightemp_08 : 32|32@1+ (1,0) [0|4294967295] "s"  MBMU

BO_ 2334195529 S2A_SUMDATA20__09: 8 SBMU
 SG_ S2A_DurationatLowtemp_09 : 0|32@1+ (1,0) [0|4294967295] "s"  MBMU
 SG_ S2A_DurationatHightemp_09 : 32|32@1+ (1,0) [0|4294967295] "s"  MBMU

BO_ 2334195530 S2A_SUMDATA20__10: 8 SBMU
 SG_ S2A_DurationatLowtemp_10 : 0|32@1+ (1,0) [0|4294967295] "s"  MBMU
 SG_ S2A_DurationatHightemp_10 : 32|32@1+ (1,0) [0|4294967295] "s"  MBMU

BO_ 2334195531 S2A_SUMDATA20__11: 8 SBMU
 SG_ S2A_DurationatLowtemp_11 : 0|32@1+ (1,0) [0|4294967295] "s"  MBMU
 SG_ S2A_DurationatHightemp_11 : 32|32@1+ (1,0) [0|4294967295] "s"  MBMU

BO_ 2334195532 S2A_SUMDATA20__12: 8 SBMU
 SG_ S2A_DurationatLowtemp_12 : 0|32@1+ (1,0) [0|4294967295] "s"  MBMU
 SG_ S2A_DurationatHightemp_12 : 32|32@1+ (1,0) [0|4294967295] "s"  MBMU

BO_ 2334195533 S2A_SUMDATA20__13: 8 SBMU
 SG_ S2A_DurationatLowtemp_13 : 0|32@1+ (1,0) [0|4294967295] "s"  MBMU
 SG_ S2A_DurationatHightemp_13 : 32|32@1+ (1,0) [0|4294967295] "s"  MBMU

BO_ 2334195534 S2A_SUMDATA20__14: 8 SBMU
 SG_ S2A_DurationatLowtemp_14 : 0|32@1+ (1,0) [0|4294967295] "s"  MBMU
 SG_ S2A_DurationatHightemp_14 : 32|32@1+ (1,0) [0|4294967295] "s"  MBMU

BO_ 2334195535 S2A_SUMDATA20__15: 8 SBMU
 SG_ S2A_DurationatLowtemp_15 : 0|32@1+ (1,0) [0|4294967295] "s"  MBMU
 SG_ S2A_DurationatHightemp_15 : 32|32@1+ (1,0) [0|4294967295] "s"  MBMU

BO_ 2334195536 S2A_SUMDATA20__16: 8 SBMU
 SG_ S2A_DurationatLowtemp_16 : 0|32@1+ (1,0) [0|4294967295] "s"  MBMU
 SG_ S2A_DurationatHightemp_16 : 32|32@1+ (1,0) [0|4294967295] "s"  MBMU

BO_ 2334195537 S2A_SUMDATA20__17: 8 SBMU
 SG_ S2A_DurationatLowtemp_17 : 0|32@1+ (1,0) [0|4294967295] "s"  MBMU
 SG_ S2A_DurationatHightemp_17 : 32|32@1+ (1,0) [0|4294967295] "s"  MBMU

BO_ 2334195538 S2A_SUMDATA20__18: 8 SBMU
 SG_ S2A_DurationatLowtemp_18 : 0|32@1+ (1,0) [0|4294967295] "s"  MBMU
 SG_ S2A_DurationatHightemp_18 : 32|32@1+ (1,0) [0|4294967295] "s"  MBMU

BO_ 2334195539 S2A_SUMDATA20__19: 8 SBMU
 SG_ S2A_DurationatLowtemp_19 : 0|32@1+ (1,0) [0|4294967295] "s"  MBMU
 SG_ S2A_DurationatHightemp_19 : 32|32@1+ (1,0) [0|4294967295] "s"  MBMU

BO_ 2334195540 S2A_SUMDATA20__20: 8 SBMU
 SG_ S2A_DurationatLowtemp_20 : 0|32@1+ (1,0) [0|4294967295] "s"  MBMU
 SG_ S2A_DurationatHightemp_20 : 32|32@1+ (1,0) [0|4294967295] "s"  MBMU

BO_ 2334195541 S2A_SUMDATA20__21: 8 SBMU
 SG_ S2A_DurationatLowtemp_21 : 0|32@1+ (1,0) [0|4294967295] "s"  MBMU
 SG_ S2A_DurationatHightemp_21 : 32|32@1+ (1,0) [0|4294967295] "s"  MBMU

BO_ 2334195542 S2A_SUMDATA20__22: 8 SBMU
 SG_ S2A_DurationatLowtemp_22 : 0|32@1+ (1,0) [0|4294967295] "s"  MBMU
 SG_ S2A_DurationatHightemp_22 : 32|32@1+ (1,0) [0|4294967295] "s"  MBMU

BO_ 2334195543 S2A_SUMDATA20__23: 8 SBMU
 SG_ S2A_DurationatLowtemp_23 : 0|32@1+ (1,0) [0|4294967295] "s"  MBMU
 SG_ S2A_DurationatHightemp_23 : 32|32@1+ (1,0) [0|4294967295] "s"  MBMU

BO_ 2334195544 S2A_SUMDATA20__24: 8 SBMU
 SG_ S2A_DurationatLowtemp_24 : 0|32@1+ (1,0) [0|4294967295] "s"  MBMU
 SG_ S2A_DurationatHightemp_24 : 32|32@1+ (1,0) [0|4294967295] "s"  MBMU

BO_ 2334195545 S2A_SUMDATA20__25: 8 SBMU
 SG_ S2A_DurationatLowtemp_25 : 0|32@1+ (1,0) [0|4294967295] "s"  MBMU
 SG_ S2A_DurationatHightemp_25 : 32|32@1+ (1,0) [0|4294967295] "s"  MBMU

BO_ 2334195546 S2A_SUMDATA20__26: 8 SBMU
 SG_ S2A_DurationatLowtemp_26 : 0|32@1+ (1,0) [0|4294967295] "s"  MBMU
 SG_ S2A_DurationatHightemp_26 : 32|32@1+ (1,0) [0|4294967295] "s"  MBMU

BO_ 2334195547 S2A_SUMDATA20__27: 8 SBMU
 SG_ S2A_DurationatLowtemp_27 : 0|32@1+ (1,0) [0|4294967295] "s"  MBMU
 SG_ S2A_DurationatHightemp_27 : 32|32@1+ (1,0) [0|4294967295] "s"  MBMU

BO_ 2334195548 S2A_SUMDATA20__28: 8 SBMU
 SG_ S2A_DurationatLowtemp_28 : 0|32@1+ (1,0) [0|4294967295] "s"  MBMU
 SG_ S2A_DurationatHightemp_28 : 32|32@1+ (1,0) [0|4294967295] "s"  MBMU

BO_ 2334195549 S2A_SUMDATA20__29: 8 SBMU
 SG_ S2A_DurationatLowtemp_29 : 0|32@1+ (1,0) [0|4294967295] "s"  MBMU
 SG_ S2A_DurationatHightemp_29 : 32|32@1+ (1,0) [0|4294967295] "s"  MBMU

BO_ 2334195550 S2A_SUMDATA20__30: 8 SBMU
 SG_ S2A_DurationatLowtemp_30 : 0|32@1+ (1,0) [0|4294967295] "s"  MBMU
 SG_ S2A_DurationatHightemp_30 : 32|32@1+ (1,0) [0|4294967295] "s"  MBMU

BO_ 2334195551 S2A_SUMDATA20__31: 8 SBMU
 SG_ S2A_DurationatLowtemp_31 : 0|32@1+ (1,0) [0|4294967295] "s"  MBMU
 SG_ S2A_DurationatHightemp_31 : 32|32@1+ (1,0) [0|4294967295] "s"  MBMU

BO_ 2334195552 S2A_SUMDATA20__32: 8 SBMU
 SG_ S2A_DurationatLowtemp_32 : 0|32@1+ (1,0) [0|4294967295] "s"  MBMU
 SG_ S2A_DurationatHightemp_32 : 32|32@1+ (1,0) [0|4294967295] "s"  MBMU

BO_ 2334195553 S2A_SUMDATA20__33: 8 SBMU
 SG_ S2A_DurationatLowtemp_33 : 0|32@1+ (1,0) [0|4294967295] "s"  MBMU
 SG_ S2A_DurationatHightemp_33 : 32|32@1+ (1,0) [0|4294967295] "s"  MBMU

BO_ 2334195554 S2A_SUMDATA20__34: 8 SBMU
 SG_ S2A_DurationatLowtemp_34 : 0|32@1+ (1,0) [0|4294967295] "s"  MBMU
 SG_ S2A_DurationatHightemp_34 : 32|32@1+ (1,0) [0|4294967295] "s"  MBMU

BO_ 2334195555 S2A_SUMDATA20__35: 8 SBMU
 SG_ S2A_DurationatLowtemp_35 : 0|32@1+ (1,0) [0|4294967295] "s"  MBMU
 SG_ S2A_DurationatHightemp_35 : 32|32@1+ (1,0) [0|4294967295] "s"  MBMU

BO_ 2334195556 S2A_SUMDATA20__36: 8 SBMU
 SG_ S2A_DurationatLowtemp_36 : 0|32@1+ (1,0) [0|4294967295] "s"  MBMU
 SG_ S2A_DurationatHightemp_36 : 32|32@1+ (1,0) [0|4294967295] "s"  MBMU

BO_ 2334195557 S2A_SUMDATA20__37: 8 SBMU
 SG_ S2A_DurationatLowtemp_37 : 0|32@1+ (1,0) [0|4294967295] "s"  MBMU
 SG_ S2A_DurationatHightemp_37 : 32|32@1+ (1,0) [0|4294967295] "s"  MBMU

BO_ 2334195558 S2A_SUMDATA20__38: 8 SBMU
 SG_ S2A_DurationatLowtemp_38 : 0|32@1+ (1,0) [0|4294967295] "s"  MBMU
 SG_ S2A_DurationatHightemp_38 : 32|32@1+ (1,0) [0|4294967295] "s"  MBMU

BO_ 2334195559 S2A_SUMDATA20__39: 8 SBMU
 SG_ S2A_DurationatLowtemp_39 : 0|32@1+ (1,0) [0|4294967295] "s"  MBMU
 SG_ S2A_DurationatHightemp_39 : 32|32@1+ (1,0) [0|4294967295] "s"  MBMU

BO_ 2334195560 S2A_SUMDATA20__40: 8 SBMU
 SG_ S2A_DurationatLowtemp_40 : 0|32@1+ (1,0) [0|4294967295] "s"  MBMU
 SG_ S2A_DurationatHightemp_40 : 32|32@1+ (1,0) [0|4294967295] "s"  MBMU

BO_ 2334195561 S2A_SUMDATA20__41: 8 SBMU
 SG_ S2A_DurationatLowtemp_41 : 0|32@1+ (1,0) [0|4294967295] "s"  MBMU
 SG_ S2A_DurationatHightemp_41 : 32|32@1+ (1,0) [0|4294967295] "s"  MBMU

BO_ 2334195562 S2A_SUMDATA20__42: 8 SBMU
 SG_ S2A_DurationatLowtemp_42 : 0|32@1+ (1,0) [0|4294967295] "s"  MBMU
 SG_ S2A_DurationatHightemp_42 : 32|32@1+ (1,0) [0|4294967295] "s"  MBMU

BO_ 2334195563 S2A_SUMDATA20__43: 8 SBMU
 SG_ S2A_DurationatLowtemp_43 : 0|32@1+ (1,0) [0|4294967295] "s"  MBMU
 SG_ S2A_DurationatHightemp_43 : 32|32@1+ (1,0) [0|4294967295] "s"  MBMU

BO_ 2334195564 S2A_SUMDATA20__44: 8 SBMU
 SG_ S2A_DurationatLowtemp_44 : 0|32@1+ (1,0) [0|4294967295] "s"  MBMU
 SG_ S2A_DurationatHightemp_44 : 32|32@1+ (1,0) [0|4294967295] "s"  MBMU

BO_ 2334195565 S2A_SUMDATA20__45: 8 SBMU
 SG_ S2A_DurationatLowtemp_45 : 0|32@1+ (1,0) [0|4294967295] "s"  MBMU
 SG_ S2A_DurationatHightemp_45 : 32|32@1+ (1,0) [0|4294967295] "s"  MBMU

BO_ 2334195566 S2A_SUMDATA20__46: 8 SBMU
 SG_ S2A_DurationatLowtemp_46 : 0|32@1+ (1,0) [0|4294967295] "s"  MBMU
 SG_ S2A_DurationatHightemp_46 : 32|32@1+ (1,0) [0|4294967295] "s"  MBMU

BO_ 2334195567 S2A_SUMDATA20__47: 8 SBMU
 SG_ S2A_DurationatLowtemp_47 : 0|32@1+ (1,0) [0|4294967295] "s"  MBMU
 SG_ S2A_DurationatHightemp_47 : 32|32@1+ (1,0) [0|4294967295] "s"  MBMU

BO_ 2334195568 S2A_SUMDATA20__48: 8 SBMU
 SG_ S2A_DurationatLowtemp_48 : 0|32@1+ (1,0) [0|4294967295] "s"  MBMU
 SG_ S2A_DurationatHightemp_48 : 32|32@1+ (1,0) [0|4294967295] "s"  MBMU

BO_ 2334195569 S2A_SUMDATA20__49: 8 SBMU
 SG_ S2A_DurationatLowtemp_49 : 0|32@1+ (1,0) [0|4294967295] "s"  MBMU
 SG_ S2A_DurationatHightemp_49 : 32|32@1+ (1,0) [0|4294967295] "s"  MBMU

BO_ 2334195570 S2A_SUMDATA20__50: 8 SBMU
 SG_ S2A_DurationatLowtemp_50 : 0|32@1+ (1,0) [0|4294967295] "s"  MBMU
 SG_ S2A_DurationatHightemp_50 : 32|32@1+ (1,0) [0|4294967295] "s"  MBMU

BO_ 2334195571 S2A_SUMDATA20__51: 8 SBMU
 SG_ S2A_DurationatLowtemp_51 : 0|32@1+ (1,0) [0|4294967295] "s"  MBMU
 SG_ S2A_DurationatHightemp_51 : 32|32@1+ (1,0) [0|4294967295] "s"  MBMU

BO_ 2334195572 S2A_SUMDATA20__52: 8 SBMU
 SG_ S2A_DurationatLowtemp_52 : 0|32@1+ (1,0) [0|4294967295] "s"  MBMU
 SG_ S2A_DurationatHightemp_52 : 32|32@1+ (1,0) [0|4294967295] "s"  MBMU

BO_ 2334195573 S2A_SUMDATA20__53: 8 SBMU
 SG_ S2A_DurationatLowtemp_53 : 0|32@1+ (1,0) [0|4294967295] "s"  MBMU
 SG_ S2A_DurationatHightemp_53 : 32|32@1+ (1,0) [0|4294967295] "s"  MBMU

BO_ 2334195574 S2A_SUMDATA20__54: 8 SBMU
 SG_ S2A_DurationatLowtemp_54 : 0|32@1+ (1,0) [0|4294967295] "s"  MBMU
 SG_ S2A_DurationatHightemp_54 : 32|32@1+ (1,0) [0|4294967295] "s"  MBMU

BO_ 2334195575 S2A_SUMDATA20__55: 8 SBMU
 SG_ S2A_DurationatLowtemp_55 : 0|32@1+ (1,0) [0|4294967295] "s"  MBMU
 SG_ S2A_DurationatHightemp_55 : 32|32@1+ (1,0) [0|4294967295] "s"  MBMU

BO_ 2334195576 S2A_SUMDATA20__56: 8 SBMU
 SG_ S2A_DurationatLowtemp_56 : 0|32@1+ (1,0) [0|4294967295] "s"  MBMU
 SG_ S2A_DurationatHightemp_56 : 32|32@1+ (1,0) [0|4294967295] "s"  MBMU

BO_ 2334195577 S2A_SUMDATA20__57: 8 SBMU
 SG_ S2A_DurationatLowtemp_57 : 0|32@1+ (1,0) [0|4294967295] "s"  MBMU
 SG_ S2A_DurationatHightemp_57 : 32|32@1+ (1,0) [0|4294967295] "s"  MBMU

BO_ 2334195578 S2A_SUMDATA20__58: 8 SBMU
 SG_ S2A_DurationatLowtemp_58 : 0|32@1+ (1,0) [0|4294967295] "s"  MBMU
 SG_ S2A_DurationatHightemp_58 : 32|32@1+ (1,0) [0|4294967295] "s"  MBMU

BO_ 2334195579 S2A_SUMDATA20__59: 8 SBMU
 SG_ S2A_DurationatLowtemp_59 : 0|32@1+ (1,0) [0|4294967295] "s"  MBMU
 SG_ S2A_DurationatHightemp_59 : 32|32@1+ (1,0) [0|4294967295] "s"  MBMU

BO_ 2334195580 S2A_SUMDATA20__60: 8 SBMU
 SG_ S2A_DurationatLowtemp_60 : 0|32@1+ (1,0) [0|4294967295] "s"  MBMU
 SG_ S2A_DurationatHightemp_60 : 32|32@1+ (1,0) [0|4294967295] "s"  MBMU

BO_ 2334195581 S2A_SUMDATA20__61: 8 SBMU
 SG_ S2A_DurationatLowtemp_61 : 0|32@1+ (1,0) [0|4294967295] "s"  MBMU
 SG_ S2A_DurationatHightemp_61 : 32|32@1+ (1,0) [0|4294967295] "s"  MBMU

BO_ 2334195582 S2A_SUMDATA20__62: 8 SBMU
 SG_ S2A_DurationatLowtemp_62 : 0|32@1+ (1,0) [0|4294967295] "s"  MBMU
 SG_ S2A_DurationatHightemp_62 : 32|32@1+ (1,0) [0|4294967295] "s"  MBMU

BO_ 2334195583 S2A_SUMDATA20__63: 8 SBMU
 SG_ S2A_DurationatLowtemp_63 : 0|32@1+ (1,0) [0|4294967295] "s"  MBMU
 SG_ S2A_DurationatHightemp_63 : 32|32@1+ (1,0) [0|4294967295] "s"  MBMU

BO_ 2334261057 S2A_SUMDATA21__01: 8 SBMU
 SG_ S2A_ChgtimesatHightemp_01 : 0|32@1+ (1,0) [0|4294967295] "s"  MBMU
 SG_ S2A_DisChgtimesatHightemp_01 : 32|32@1+ (1,0) [0|4294967295] "s"  MBMU

BO_ 2334261058 S2A_SUMDATA21__02: 8 SBMU
 SG_ S2A_ChgtimesatHightemp_02 : 0|32@1+ (1,0) [0|4294967295] "s"  MBMU
 SG_ S2A_DisChgtimesatHightemp_02 : 32|32@1+ (1,0) [0|4294967295] "s"  MBMU

BO_ 2334261059 S2A_SUMDATA21__03: 8 SBMU
 SG_ S2A_ChgtimesatHightemp_03 : 0|32@1+ (1,0) [0|4294967295] "s"  MBMU
 SG_ S2A_DisChgtimesatHightemp_03 : 32|32@1+ (1,0) [0|4294967295] "s"  MBMU

BO_ 2334261060 S2A_SUMDATA21__04: 8 SBMU
 SG_ S2A_ChgtimesatHightemp_04 : 0|32@1+ (1,0) [0|4294967295] "s"  MBMU
 SG_ S2A_DisChgtimesatHightemp_04 : 32|32@1+ (1,0) [0|4294967295] "s"  MBMU

BO_ 2334261061 S2A_SUMDATA21__05: 8 SBMU
 SG_ S2A_ChgtimesatHightemp_05 : 0|32@1+ (1,0) [0|4294967295] "s"  MBMU
 SG_ S2A_DisChgtimesatHightemp_05 : 32|32@1+ (1,0) [0|4294967295] "s"  MBMU

BO_ 2334261062 S2A_SUMDATA21__06: 8 SBMU
 SG_ S2A_ChgtimesatHightemp_06 : 0|32@1+ (1,0) [0|4294967295] "s"  MBMU
 SG_ S2A_DisChgtimesatHightemp_06 : 32|32@1+ (1,0) [0|4294967295] "s"  MBMU

BO_ 2334261063 S2A_SUMDATA21__07: 8 SBMU
 SG_ S2A_ChgtimesatHightemp_07 : 0|32@1+ (1,0) [0|4294967295] "s"  MBMU
 SG_ S2A_DisChgtimesatHightemp_07 : 32|32@1+ (1,0) [0|4294967295] "s"  MBMU

BO_ 2334261064 S2A_SUMDATA21__08: 8 SBMU
 SG_ S2A_ChgtimesatHightemp_08 : 0|32@1+ (1,0) [0|4294967295] "s"  MBMU
 SG_ S2A_DisChgtimesatHightemp_08 : 32|32@1+ (1,0) [0|4294967295] "s"  MBMU

BO_ 2334261065 S2A_SUMDATA21__09: 8 SBMU
 SG_ S2A_ChgtimesatHightemp_09 : 0|32@1+ (1,0) [0|4294967295] "s"  MBMU
 SG_ S2A_DisChgtimesatHightemp_09 : 32|32@1+ (1,0) [0|4294967295] "s"  MBMU

BO_ 2334261066 S2A_SUMDATA21__10: 8 SBMU
 SG_ S2A_ChgtimesatHightemp_10 : 0|32@1+ (1,0) [0|4294967295] "s"  MBMU
 SG_ S2A_DisChgtimesatHightemp_10 : 32|32@1+ (1,0) [0|4294967295] "s"  MBMU

BO_ 2334261067 S2A_SUMDATA21__11: 8 SBMU
 SG_ S2A_ChgtimesatHightemp_11 : 0|32@1+ (1,0) [0|4294967295] "s"  MBMU
 SG_ S2A_DisChgtimesatHightemp_11 : 32|32@1+ (1,0) [0|4294967295] "s"  MBMU

BO_ 2334261068 S2A_SUMDATA21__12: 8 SBMU
 SG_ S2A_ChgtimesatHightemp_12 : 0|32@1+ (1,0) [0|4294967295] "s"  MBMU
 SG_ S2A_DisChgtimesatHightemp_12 : 32|32@1+ (1,0) [0|4294967295] "s"  MBMU

BO_ 2334261069 S2A_SUMDATA21__13: 8 SBMU
 SG_ S2A_ChgtimesatHightemp_13 : 0|32@1+ (1,0) [0|4294967295] "s"  MBMU
 SG_ S2A_DisChgtimesatHightemp_13 : 32|32@1+ (1,0) [0|4294967295] "s"  MBMU

BO_ 2334261070 S2A_SUMDATA21__14: 8 SBMU
 SG_ S2A_ChgtimesatHightemp_14 : 0|32@1+ (1,0) [0|4294967295] "s"  MBMU
 SG_ S2A_DisChgtimesatHightemp_14 : 32|32@1+ (1,0) [0|4294967295] "s"  MBMU

BO_ 2334261071 S2A_SUMDATA21__15: 8 SBMU
 SG_ S2A_ChgtimesatHightemp_15 : 0|32@1+ (1,0) [0|4294967295] "s"  MBMU
 SG_ S2A_DisChgtimesatHightemp_15 : 32|32@1+ (1,0) [0|4294967295] "s"  MBMU

BO_ 2334261072 S2A_SUMDATA21__16: 8 SBMU
 SG_ S2A_ChgtimesatHightemp_16 : 0|32@1+ (1,0) [0|4294967295] "s"  MBMU
 SG_ S2A_DisChgtimesatHightemp_16 : 32|32@1+ (1,0) [0|4294967295] "s"  MBMU

BO_ 2334261073 S2A_SUMDATA21__17: 8 SBMU
 SG_ S2A_ChgtimesatHightemp_17 : 0|32@1+ (1,0) [0|4294967295] "s"  MBMU
 SG_ S2A_DisChgtimesatHightemp_17 : 32|32@1+ (1,0) [0|4294967295] "s"  MBMU

BO_ 2334261074 S2A_SUMDATA21__18: 8 SBMU
 SG_ S2A_ChgtimesatHightemp_18 : 0|32@1+ (1,0) [0|4294967295] "s"  MBMU
 SG_ S2A_DisChgtimesatHightemp_18 : 32|32@1+ (1,0) [0|4294967295] "s"  MBMU

BO_ 2334261075 S2A_SUMDATA21__19: 8 SBMU
 SG_ S2A_ChgtimesatHightemp_19 : 0|32@1+ (1,0) [0|4294967295] "s"  MBMU
 SG_ S2A_DisChgtimesatHightemp_19 : 32|32@1+ (1,0) [0|4294967295] "s"  MBMU

BO_ 2334261076 S2A_SUMDATA21__20: 8 SBMU
 SG_ S2A_ChgtimesatHightemp_20 : 0|32@1+ (1,0) [0|4294967295] "s"  MBMU
 SG_ S2A_DisChgtimesatHightemp_20 : 32|32@1+ (1,0) [0|4294967295] "s"  MBMU

BO_ 2334261077 S2A_SUMDATA21__21: 8 SBMU
 SG_ S2A_ChgtimesatHightemp_21 : 0|32@1+ (1,0) [0|4294967295] "s"  MBMU
 SG_ S2A_DisChgtimesatHightemp_21 : 32|32@1+ (1,0) [0|4294967295] "s"  MBMU

BO_ 2334261078 S2A_SUMDATA21__22: 8 SBMU
 SG_ S2A_ChgtimesatHightemp_22 : 0|32@1+ (1,0) [0|4294967295] "s"  MBMU
 SG_ S2A_DisChgtimesatHightemp_22 : 32|32@1+ (1,0) [0|4294967295] "s"  MBMU

BO_ 2334261079 S2A_SUMDATA21__23: 8 SBMU
 SG_ S2A_ChgtimesatHightemp_23 : 0|32@1+ (1,0) [0|4294967295] "s"  MBMU
 SG_ S2A_DisChgtimesatHightemp_23 : 32|32@1+ (1,0) [0|4294967295] "s"  MBMU

BO_ 2334261080 S2A_SUMDATA21__24: 8 SBMU
 SG_ S2A_ChgtimesatHightemp_24 : 0|32@1+ (1,0) [0|4294967295] "s"  MBMU
 SG_ S2A_DisChgtimesatHightemp_24 : 32|32@1+ (1,0) [0|4294967295] "s"  MBMU

BO_ 2334261081 S2A_SUMDATA21__25: 8 SBMU
 SG_ S2A_ChgtimesatHightemp_25 : 0|32@1+ (1,0) [0|4294967295] "s"  MBMU
 SG_ S2A_DisChgtimesatHightemp_25 : 32|32@1+ (1,0) [0|4294967295] "s"  MBMU

BO_ 2334261082 S2A_SUMDATA21__26: 8 SBMU
 SG_ S2A_ChgtimesatHightemp_26 : 0|32@1+ (1,0) [0|4294967295] "s"  MBMU
 SG_ S2A_DisChgtimesatHightemp_26 : 32|32@1+ (1,0) [0|4294967295] "s"  MBMU

BO_ 2334261083 S2A_SUMDATA21__27: 8 SBMU
 SG_ S2A_ChgtimesatHightemp_27 : 0|32@1+ (1,0) [0|4294967295] "s"  MBMU
 SG_ S2A_DisChgtimesatHightemp_27 : 32|32@1+ (1,0) [0|4294967295] "s"  MBMU

BO_ 2334261084 S2A_SUMDATA21__28: 8 SBMU
 SG_ S2A_ChgtimesatHightemp_28 : 0|32@1+ (1,0) [0|4294967295] "s"  MBMU
 SG_ S2A_DisChgtimesatHightemp_28 : 32|32@1+ (1,0) [0|4294967295] "s"  MBMU

BO_ 2334261085 S2A_SUMDATA21__29: 8 SBMU
 SG_ S2A_ChgtimesatHightemp_29 : 0|32@1+ (1,0) [0|4294967295] "s"  MBMU
 SG_ S2A_DisChgtimesatHightemp_29 : 32|32@1+ (1,0) [0|4294967295] "s"  MBMU

BO_ 2334261086 S2A_SUMDATA21__30: 8 SBMU
 SG_ S2A_ChgtimesatHightemp_30 : 0|32@1+ (1,0) [0|4294967295] "s"  MBMU
 SG_ S2A_DisChgtimesatHightemp_30 : 32|32@1+ (1,0) [0|4294967295] "s"  MBMU

BO_ 2334261087 S2A_SUMDATA21__31: 8 SBMU
 SG_ S2A_ChgtimesatHightemp_31 : 0|32@1+ (1,0) [0|4294967295] "s"  MBMU
 SG_ S2A_DisChgtimesatHightemp_31 : 32|32@1+ (1,0) [0|4294967295] "s"  MBMU

BO_ 2334261088 S2A_SUMDATA21__32: 8 SBMU
 SG_ S2A_ChgtimesatHightemp_32 : 0|32@1+ (1,0) [0|4294967295] "s"  MBMU
 SG_ S2A_DisChgtimesatHightemp_32 : 32|32@1+ (1,0) [0|4294967295] "s"  MBMU

BO_ 2334261089 S2A_SUMDATA21__33: 8 SBMU
 SG_ S2A_ChgtimesatHightemp_33 : 0|32@1+ (1,0) [0|4294967295] "s"  MBMU
 SG_ S2A_DisChgtimesatHightemp_33 : 32|32@1+ (1,0) [0|4294967295] "s"  MBMU

BO_ 2334261090 S2A_SUMDATA21__34: 8 SBMU
 SG_ S2A_ChgtimesatHightemp_34 : 0|32@1+ (1,0) [0|4294967295] "s"  MBMU
 SG_ S2A_DisChgtimesatHightemp_34 : 32|32@1+ (1,0) [0|4294967295] "s"  MBMU

BO_ 2334261091 S2A_SUMDATA21__35: 8 SBMU
 SG_ S2A_ChgtimesatHightemp_35 : 0|32@1+ (1,0) [0|4294967295] "s"  MBMU
 SG_ S2A_DisChgtimesatHightemp_35 : 32|32@1+ (1,0) [0|4294967295] "s"  MBMU

BO_ 2334261092 S2A_SUMDATA21__36: 8 SBMU
 SG_ S2A_ChgtimesatHightemp_36 : 0|32@1+ (1,0) [0|4294967295] "s"  MBMU
 SG_ S2A_DisChgtimesatHightemp_36 : 32|32@1+ (1,0) [0|4294967295] "s"  MBMU

BO_ 2334261093 S2A_SUMDATA21__37: 8 SBMU
 SG_ S2A_ChgtimesatHightemp_37 : 0|32@1+ (1,0) [0|4294967295] "s"  MBMU
 SG_ S2A_DisChgtimesatHightemp_37 : 32|32@1+ (1,0) [0|4294967295] "s"  MBMU

BO_ 2334261094 S2A_SUMDATA21__38: 8 SBMU
 SG_ S2A_ChgtimesatHightemp_38 : 0|32@1+ (1,0) [0|4294967295] "s"  MBMU
 SG_ S2A_DisChgtimesatHightemp_38 : 32|32@1+ (1,0) [0|4294967295] "s"  MBMU

BO_ 2334261095 S2A_SUMDATA21__39: 8 SBMU
 SG_ S2A_ChgtimesatHightemp_39 : 0|32@1+ (1,0) [0|4294967295] "s"  MBMU
 SG_ S2A_DisChgtimesatHightemp_39 : 32|32@1+ (1,0) [0|4294967295] "s"  MBMU

BO_ 2334261096 S2A_SUMDATA21__40: 8 SBMU
 SG_ S2A_ChgtimesatHightemp_40 : 0|32@1+ (1,0) [0|4294967295] "s"  MBMU
 SG_ S2A_DisChgtimesatHightemp_40 : 32|32@1+ (1,0) [0|4294967295] "s"  MBMU

BO_ 2334261097 S2A_SUMDATA21__41: 8 SBMU
 SG_ S2A_ChgtimesatHightemp_41 : 0|32@1+ (1,0) [0|4294967295] "s"  MBMU
 SG_ S2A_DisChgtimesatHightemp_41 : 32|32@1+ (1,0) [0|4294967295] "s"  MBMU

BO_ 2334261098 S2A_SUMDATA21__42: 8 SBMU
 SG_ S2A_ChgtimesatHightemp_42 : 0|32@1+ (1,0) [0|4294967295] "s"  MBMU
 SG_ S2A_DisChgtimesatHightemp_42 : 32|32@1+ (1,0) [0|4294967295] "s"  MBMU

BO_ 2334261099 S2A_SUMDATA21__43: 8 SBMU
 SG_ S2A_ChgtimesatHightemp_43 : 0|32@1+ (1,0) [0|4294967295] "s"  MBMU
 SG_ S2A_DisChgtimesatHightemp_43 : 32|32@1+ (1,0) [0|4294967295] "s"  MBMU

BO_ 2334261100 S2A_SUMDATA21__44: 8 SBMU
 SG_ S2A_ChgtimesatHightemp_44 : 0|32@1+ (1,0) [0|4294967295] "s"  MBMU
 SG_ S2A_DisChgtimesatHightemp_44 : 32|32@1+ (1,0) [0|4294967295] "s"  MBMU

BO_ 2334261101 S2A_SUMDATA21__45: 8 SBMU
 SG_ S2A_ChgtimesatHightemp_45 : 0|32@1+ (1,0) [0|4294967295] "s"  MBMU
 SG_ S2A_DisChgtimesatHightemp_45 : 32|32@1+ (1,0) [0|4294967295] "s"  MBMU

BO_ 2334261102 S2A_SUMDATA21__46: 8 SBMU
 SG_ S2A_ChgtimesatHightemp_46 : 0|32@1+ (1,0) [0|4294967295] "s"  MBMU
 SG_ S2A_DisChgtimesatHightemp_46 : 32|32@1+ (1,0) [0|4294967295] "s"  MBMU

BO_ 2334261103 S2A_SUMDATA21__47: 8 SBMU
 SG_ S2A_ChgtimesatHightemp_47 : 0|32@1+ (1,0) [0|4294967295] "s"  MBMU
 SG_ S2A_DisChgtimesatHightemp_47 : 32|32@1+ (1,0) [0|4294967295] "s"  MBMU

BO_ 2334261104 S2A_SUMDATA21__48: 8 SBMU
 SG_ S2A_ChgtimesatHightemp_48 : 0|32@1+ (1,0) [0|4294967295] "s"  MBMU
 SG_ S2A_DisChgtimesatHightemp_48 : 32|32@1+ (1,0) [0|4294967295] "s"  MBMU

BO_ 2334261105 S2A_SUMDATA21__49: 8 SBMU
 SG_ S2A_ChgtimesatHightemp_49 : 0|32@1+ (1,0) [0|4294967295] "s"  MBMU
 SG_ S2A_DisChgtimesatHightemp_49 : 32|32@1+ (1,0) [0|4294967295] "s"  MBMU

BO_ 2334261106 S2A_SUMDATA21__50: 8 SBMU
 SG_ S2A_ChgtimesatHightemp_50 : 0|32@1+ (1,0) [0|4294967295] "s"  MBMU
 SG_ S2A_DisChgtimesatHightemp_50 : 32|32@1+ (1,0) [0|4294967295] "s"  MBMU

BO_ 2334261107 S2A_SUMDATA21__51: 8 SBMU
 SG_ S2A_ChgtimesatHightemp_51 : 0|32@1+ (1,0) [0|4294967295] "s"  MBMU
 SG_ S2A_DisChgtimesatHightemp_51 : 32|32@1+ (1,0) [0|4294967295] "s"  MBMU

BO_ 2334261108 S2A_SUMDATA21__52: 8 SBMU
 SG_ S2A_ChgtimesatHightemp_52 : 0|32@1+ (1,0) [0|4294967295] "s"  MBMU
 SG_ S2A_DisChgtimesatHightemp_52 : 32|32@1+ (1,0) [0|4294967295] "s"  MBMU

BO_ 2334261109 S2A_SUMDATA21__53: 8 SBMU
 SG_ S2A_ChgtimesatHightemp_53 : 0|32@1+ (1,0) [0|4294967295] "s"  MBMU
 SG_ S2A_DisChgtimesatHightemp_53 : 32|32@1+ (1,0) [0|4294967295] "s"  MBMU

BO_ 2334261110 S2A_SUMDATA21__54: 8 SBMU
 SG_ S2A_ChgtimesatHightemp_54 : 0|32@1+ (1,0) [0|4294967295] "s"  MBMU
 SG_ S2A_DisChgtimesatHightemp_54 : 32|32@1+ (1,0) [0|4294967295] "s"  MBMU

BO_ 2334261111 S2A_SUMDATA21__55: 8 SBMU
 SG_ S2A_ChgtimesatHightemp_55 : 0|32@1+ (1,0) [0|4294967295] "s"  MBMU
 SG_ S2A_DisChgtimesatHightemp_55 : 32|32@1+ (1,0) [0|4294967295] "s"  MBMU

BO_ 2334261112 S2A_SUMDATA21__56: 8 SBMU
 SG_ S2A_ChgtimesatHightemp_56 : 0|32@1+ (1,0) [0|4294967295] "s"  MBMU
 SG_ S2A_DisChgtimesatHightemp_56 : 32|32@1+ (1,0) [0|4294967295] "s"  MBMU

BO_ 2334261113 S2A_SUMDATA21__57: 8 SBMU
 SG_ S2A_ChgtimesatHightemp_57 : 0|32@1+ (1,0) [0|4294967295] "s"  MBMU
 SG_ S2A_DisChgtimesatHightemp_57 : 32|32@1+ (1,0) [0|4294967295] "s"  MBMU

BO_ 2334261114 S2A_SUMDATA21__58: 8 SBMU
 SG_ S2A_ChgtimesatHightemp_58 : 0|32@1+ (1,0) [0|4294967295] "s"  MBMU
 SG_ S2A_DisChgtimesatHightemp_58 : 32|32@1+ (1,0) [0|4294967295] "s"  MBMU

BO_ 2334261115 S2A_SUMDATA21__59: 8 SBMU
 SG_ S2A_ChgtimesatHightemp_59 : 0|32@1+ (1,0) [0|4294967295] "s"  MBMU
 SG_ S2A_DisChgtimesatHightemp_59 : 32|32@1+ (1,0) [0|4294967295] "s"  MBMU

BO_ 2334261116 S2A_SUMDATA21__60: 8 SBMU
 SG_ S2A_ChgtimesatHightemp_60 : 0|32@1+ (1,0) [0|4294967295] "s"  MBMU
 SG_ S2A_DisChgtimesatHightemp_60 : 32|32@1+ (1,0) [0|4294967295] "s"  MBMU

BO_ 2334261117 S2A_SUMDATA21__61: 8 SBMU
 SG_ S2A_ChgtimesatHightemp_61 : 0|32@1+ (1,0) [0|4294967295] "s"  MBMU
 SG_ S2A_DisChgtimesatHightemp_61 : 32|32@1+ (1,0) [0|4294967295] "s"  MBMU

BO_ 2334261118 S2A_SUMDATA21__62: 8 SBMU
 SG_ S2A_ChgtimesatHightemp_62 : 0|32@1+ (1,0) [0|4294967295] "s"  MBMU
 SG_ S2A_DisChgtimesatHightemp_62 : 32|32@1+ (1,0) [0|4294967295] "s"  MBMU

BO_ 2334261119 S2A_SUMDATA21__63: 8 SBMU
 SG_ S2A_ChgtimesatHightemp_63 : 0|32@1+ (1,0) [0|4294967295] "s"  MBMU
 SG_ S2A_DisChgtimesatHightemp_63 : 32|32@1+ (1,0) [0|4294967295] "s"  MBMU

BO_ 2332880529 M2P_SUMDATA12__01: 8 MBMU
 SG_ M2P_STofSBMUAutoCoding_01 : 1|4@1+ (1,0) [0|15] ""  PC

BO_ 2332880530 M2P_SUMDATA12__02: 8 MBMU
 SG_ M2P_STofSBMUAutoCoding_02 : 1|4@1+ (1,0) [0|15] ""  PC

BO_ 2332880531 M2P_SUMDATA12__03: 8 MBMU
 SG_ M2P_STofSBMUAutoCoding_03 : 1|4@1+ (1,0) [0|15] ""  PC

BO_ 2332880532 M2P_SUMDATA12__04: 8 MBMU
 SG_ M2P_STofSBMUAutoCoding_04 : 1|4@1+ (1,0) [0|15] ""  PC

BO_ 2332880533 M2P_SUMDATA12__05: 8 MBMU
 SG_ M2P_STofSBMUAutoCoding_05 : 1|4@1+ (1,0) [0|15] ""  PC

BO_ 2332880534 M2P_SUMDATA12__06: 8 MBMU
 SG_ M2P_STofSBMUAutoCoding_06 : 1|4@1+ (1,0) [0|15] ""  PC

BO_ 2332880535 M2P_SUMDATA12__07: 8 MBMU
 SG_ M2P_STofSBMUAutoCoding_07 : 1|4@1+ (1,0) [0|15] ""  PC

BO_ 2332880536 M2P_SUMDATA12__08: 8 MBMU
 SG_ M2P_STofSBMUAutoCoding_08 : 1|4@1+ (1,0) [0|15] ""  PC

BO_ 2332880537 M2P_SUMDATA12__09: 8 MBMU
 SG_ M2P_STofSBMUAutoCoding_09 : 1|4@1+ (1,0) [0|15] ""  PC

BO_ 2332880538 M2P_SUMDATA12__10: 8 MBMU
 SG_ M2P_STofSBMUAutoCoding_10 : 1|4@1+ (1,0) [0|15] ""  PC

BO_ 2332880539 M2P_SUMDATA12__11: 8 MBMU
 SG_ M2P_STofSBMUAutoCoding_11 : 1|4@1+ (1,0) [0|15] ""  PC

BO_ 2332880540 M2P_SUMDATA12__12: 8 MBMU
 SG_ M2P_STofSBMUAutoCoding_12 : 1|4@1+ (1,0) [0|15] ""  PC

BO_ 2332880541 M2P_SUMDATA12__13: 8 MBMU
 SG_ M2P_STofSBMUAutoCoding_13 : 1|4@1+ (1,0) [0|15] ""  PC

BO_ 2332880542 M2P_SUMDATA12__14: 8 MBMU
 SG_ M2P_STofSBMUAutoCoding_14 : 1|4@1+ (1,0) [0|15] ""  PC

BO_ 2332880543 M2P_SUMDATA12__15: 8 MBMU
 SG_ M2P_STofSBMUAutoCoding_15 : 1|4@1+ (1,0) [0|15] ""  PC

BO_ 2332880544 M2P_SUMDATA12__16: 8 MBMU
 SG_ M2P_STofSBMUAutoCoding_16 : 1|4@1+ (1,0) [0|15] ""  PC

BO_ 2332880545 M2P_SUMDATA12__17: 8 MBMU
 SG_ M2P_STofSBMUAutoCoding_17 : 1|4@1+ (1,0) [0|15] ""  PC

BO_ 2332880546 M2P_SUMDATA12__18: 8 MBMU
 SG_ M2P_STofSBMUAutoCoding_18 : 1|4@1+ (1,0) [0|15] ""  PC

BO_ 2332880547 M2P_SUMDATA12__19: 8 MBMU
 SG_ M2P_STofSBMUAutoCoding_19 : 1|4@1+ (1,0) [0|15] ""  PC

BO_ 2332880548 M2P_SUMDATA12__20: 8 MBMU
 SG_ M2P_STofSBMUAutoCoding_20 : 1|4@1+ (1,0) [0|15] ""  PC

BO_ 2332880549 M2P_SUMDATA12__21: 8 MBMU
 SG_ M2P_STofSBMUAutoCoding_21 : 1|4@1+ (1,0) [0|15] ""  PC

BO_ 2332880550 M2P_SUMDATA12__22: 8 MBMU
 SG_ M2P_STofSBMUAutoCoding_22 : 1|4@1+ (1,0) [0|15] ""  PC

BO_ 2332880551 M2P_SUMDATA12__23: 8 MBMU
 SG_ M2P_STofSBMUAutoCoding_23 : 1|4@1+ (1,0) [0|15] ""  PC

BO_ 2332880552 M2P_SUMDATA12__24: 8 MBMU
 SG_ M2P_STofSBMUAutoCoding_24 : 1|4@1+ (1,0) [0|15] ""  PC

BO_ 2332880553 M2P_SUMDATA12__25: 8 MBMU
 SG_ M2P_STofSBMUAutoCoding_25 : 1|4@1+ (1,0) [0|15] ""  PC

BO_ 2332880554 M2P_SUMDATA12__26: 8 MBMU
 SG_ M2P_STofSBMUAutoCoding_26 : 1|4@1+ (1,0) [0|15] ""  PC

BO_ 2332880555 M2P_SUMDATA12__27: 8 MBMU
 SG_ M2P_STofSBMUAutoCoding_27 : 1|4@1+ (1,0) [0|15] ""  PC

BO_ 2332880556 M2P_SUMDATA12__28: 8 MBMU
 SG_ M2P_STofSBMUAutoCoding_28 : 1|4@1+ (1,0) [0|15] ""  PC

BO_ 2332880557 M2P_SUMDATA12__29: 8 MBMU
 SG_ M2P_STofSBMUAutoCoding_29 : 1|4@1+ (1,0) [0|15] ""  PC

BO_ 2332880558 M2P_SUMDATA12__30: 8 MBMU
 SG_ M2P_STofSBMUAutoCoding_30 : 1|4@1+ (1,0) [0|15] ""  PC

BO_ 2332880559 M2P_SUMDATA12__31: 8 MBMU
 SG_ M2P_STofSBMUAutoCoding_31 : 1|4@1+ (1,0) [0|15] ""  PC

BO_ 2165411822 P2A_CMD: 8 PC
 SG_ P2A_CMD_StepChrSwitch : 0|2@1+ (1,0) [0|3] ""  PC

BO_ 2484137617 E2M_CMD: 8 ETH
 SG_ E2M_CMD_BlackStart : 0|2@1+ (1,0) [0|3] ""  MBMU,SBMU
 SG_ E2M_CMD_TMSPowerOff : 2|1@1+ (1,0) [0|1] ""  MBMU,SBMU

BO_ 2418077249 S2P_Lmt15__01: 8 SBMU
 SG_ S2P_Lmt15_Over_UModule1_01 : 0|16@1+ (0.1,0) [0|6553.5] "V"  PC
 SG_ S2P_Lmt15_Over_RModule1_01 : 16|16@1+ (0.1,0) [0|6553.5] "V"  PC
 SG_ S2P_Lmt15_Over_UModule2_01 : 32|16@1+ (0.1,0) [0|6553.5] "V"  PC
 SG_ S2P_Lmt15_Over_RModule2_01 : 48|16@1+ (0.1,0) [0|6553.5] "V"  PC

BO_ 2418077250 S2P_Lmt15__02: 8 SBMU
 SG_ S2P_Lmt15_Over_UModule1_02 : 0|16@1+ (0.1,0) [0|6553.5] "V"  PC
 SG_ S2P_Lmt15_Over_RModule1_02 : 16|16@1+ (0.1,0) [0|6553.5] "V"  PC
 SG_ S2P_Lmt15_Over_UModule2_02 : 32|16@1+ (0.1,0) [0|6553.5] "V"  PC
 SG_ S2P_Lmt15_Over_RModule2_02 : 48|16@1+ (0.1,0) [0|6553.5] "V"  PC

BO_ 2418077251 S2P_Lmt15__03: 8 SBMU
 SG_ S2P_Lmt15_Over_UModule1_03 : 0|16@1+ (0.1,0) [0|6553.5] "V"  PC
 SG_ S2P_Lmt15_Over_RModule1_03 : 16|16@1+ (0.1,0) [0|6553.5] "V"  PC
 SG_ S2P_Lmt15_Over_UModule2_03 : 32|16@1+ (0.1,0) [0|6553.5] "V"  PC
 SG_ S2P_Lmt15_Over_RModule2_03 : 48|16@1+ (0.1,0) [0|6553.5] "V"  PC

BO_ 2418077252 S2P_Lmt15__04: 8 SBMU
 SG_ S2P_Lmt15_Over_UModule1_04 : 0|16@1+ (0.1,0) [0|6553.5] "V"  PC
 SG_ S2P_Lmt15_Over_RModule1_04 : 16|16@1+ (0.1,0) [0|6553.5] "V"  PC
 SG_ S2P_Lmt15_Over_UModule2_04 : 32|16@1+ (0.1,0) [0|6553.5] "V"  PC
 SG_ S2P_Lmt15_Over_RModule2_04 : 48|16@1+ (0.1,0) [0|6553.5] "V"  PC

BO_ 2418077253 S2P_Lmt15__05: 8 SBMU
 SG_ S2P_Lmt15_Over_UModule1_05 : 0|16@1+ (0.1,0) [0|6553.5] "V"  PC
 SG_ S2P_Lmt15_Over_RModule1_05 : 16|16@1+ (0.1,0) [0|6553.5] "V"  PC
 SG_ S2P_Lmt15_Over_UModule2_05 : 32|16@1+ (0.1,0) [0|6553.5] "V"  PC
 SG_ S2P_Lmt15_Over_RModule2_05 : 48|16@1+ (0.1,0) [0|6553.5] "V"  PC

BO_ 2418077254 S2P_Lmt15__06: 8 SBMU
 SG_ S2P_Lmt15_Over_UModule1_06 : 0|16@1+ (0.1,0) [0|6553.5] "V"  PC
 SG_ S2P_Lmt15_Over_RModule1_06 : 16|16@1+ (0.1,0) [0|6553.5] "V"  PC
 SG_ S2P_Lmt15_Over_UModule2_06 : 32|16@1+ (0.1,0) [0|6553.5] "V"  PC
 SG_ S2P_Lmt15_Over_RModule2_06 : 48|16@1+ (0.1,0) [0|6553.5] "V"  PC

BO_ 2418077255 S2P_Lmt15__07: 8 SBMU
 SG_ S2P_Lmt15_Over_UModule1_07 : 0|16@1+ (0.1,0) [0|6553.5] "V"  PC
 SG_ S2P_Lmt15_Over_RModule1_07 : 16|16@1+ (0.1,0) [0|6553.5] "V"  PC
 SG_ S2P_Lmt15_Over_UModule2_07 : 32|16@1+ (0.1,0) [0|6553.5] "V"  PC
 SG_ S2P_Lmt15_Over_RModule2_07 : 48|16@1+ (0.1,0) [0|6553.5] "V"  PC

BO_ 2418077256 S2P_Lmt15__08: 8 SBMU
 SG_ S2P_Lmt15_Over_UModule1_08 : 0|16@1+ (0.1,0) [0|6553.5] "V"  PC
 SG_ S2P_Lmt15_Over_RModule1_08 : 16|16@1+ (0.1,0) [0|6553.5] "V"  PC
 SG_ S2P_Lmt15_Over_UModule2_08 : 32|16@1+ (0.1,0) [0|6553.5] "V"  PC
 SG_ S2P_Lmt15_Over_RModule2_08 : 48|16@1+ (0.1,0) [0|6553.5] "V"  PC

BO_ 2418077257 S2P_Lmt15__09: 8 SBMU
 SG_ S2P_Lmt15_Over_UModule1_09 : 0|16@1+ (0.1,0) [0|6553.5] "V"  PC
 SG_ S2P_Lmt15_Over_RModule1_09 : 16|16@1+ (0.1,0) [0|6553.5] "V"  PC
 SG_ S2P_Lmt15_Over_UModule2_09 : 32|16@1+ (0.1,0) [0|6553.5] "V"  PC
 SG_ S2P_Lmt15_Over_RModule2_09 : 48|16@1+ (0.1,0) [0|6553.5] "V"  PC

BO_ 2418077258 S2P_Lmt15__10: 8 SBMU
 SG_ S2P_Lmt15_Over_UModule1_10 : 0|16@1+ (0.1,0) [0|6553.5] "V"  PC
 SG_ S2P_Lmt15_Over_RModule1_10 : 16|16@1+ (0.1,0) [0|6553.5] "V"  PC
 SG_ S2P_Lmt15_Over_UModule2_10 : 32|16@1+ (0.1,0) [0|6553.5] "V"  PC
 SG_ S2P_Lmt15_Over_RModule2_10 : 48|16@1+ (0.1,0) [0|6553.5] "V"  PC

BO_ 2418077259 S2P_Lmt15__11: 8 SBMU
 SG_ S2P_Lmt15_Over_UModule1_11 : 0|16@1+ (0.1,0) [0|6553.5] "V"  PC
 SG_ S2P_Lmt15_Over_RModule1_11 : 16|16@1+ (0.1,0) [0|6553.5] "V"  PC
 SG_ S2P_Lmt15_Over_UModule2_11 : 32|16@1+ (0.1,0) [0|6553.5] "V"  PC
 SG_ S2P_Lmt15_Over_RModule2_11 : 48|16@1+ (0.1,0) [0|6553.5] "V"  PC

BO_ 2418077260 S2P_Lmt15__12: 8 SBMU
 SG_ S2P_Lmt15_Over_UModule1_12 : 0|16@1+ (0.1,0) [0|6553.5] "V"  PC
 SG_ S2P_Lmt15_Over_RModule1_12 : 16|16@1+ (0.1,0) [0|6553.5] "V"  PC
 SG_ S2P_Lmt15_Over_UModule2_12 : 32|16@1+ (0.1,0) [0|6553.5] "V"  PC
 SG_ S2P_Lmt15_Over_RModule2_12 : 48|16@1+ (0.1,0) [0|6553.5] "V"  PC

BO_ 2418077261 S2P_Lmt15__13: 8 SBMU
 SG_ S2P_Lmt15_Over_UModule1_13 : 0|16@1+ (0.1,0) [0|6553.5] "V"  PC
 SG_ S2P_Lmt15_Over_RModule1_13 : 16|16@1+ (0.1,0) [0|6553.5] "V"  PC
 SG_ S2P_Lmt15_Over_UModule2_13 : 32|16@1+ (0.1,0) [0|6553.5] "V"  PC
 SG_ S2P_Lmt15_Over_RModule2_13 : 48|16@1+ (0.1,0) [0|6553.5] "V"  PC

BO_ 2418077262 S2P_Lmt15__14: 8 SBMU
 SG_ S2P_Lmt15_Over_UModule1_14 : 0|16@1+ (0.1,0) [0|6553.5] "V"  PC
 SG_ S2P_Lmt15_Over_RModule1_14 : 16|16@1+ (0.1,0) [0|6553.5] "V"  PC
 SG_ S2P_Lmt15_Over_UModule2_14 : 32|16@1+ (0.1,0) [0|6553.5] "V"  PC
 SG_ S2P_Lmt15_Over_RModule2_14 : 48|16@1+ (0.1,0) [0|6553.5] "V"  PC

BO_ 2418077263 S2P_Lmt15__15: 8 SBMU
 SG_ S2P_Lmt15_Over_UModule1_15 : 0|16@1+ (0.1,0) [0|6553.5] "V"  PC
 SG_ S2P_Lmt15_Over_RModule1_15 : 16|16@1+ (0.1,0) [0|6553.5] "V"  PC
 SG_ S2P_Lmt15_Over_UModule2_15 : 32|16@1+ (0.1,0) [0|6553.5] "V"  PC
 SG_ S2P_Lmt15_Over_RModule2_15 : 48|16@1+ (0.1,0) [0|6553.5] "V"  PC

BO_ 2418077264 S2P_Lmt15__16: 8 SBMU
 SG_ S2P_Lmt15_Over_UModule1_16 : 0|16@1+ (0.1,0) [0|6553.5] "V"  PC
 SG_ S2P_Lmt15_Over_RModule1_16 : 16|16@1+ (0.1,0) [0|6553.5] "V"  PC
 SG_ S2P_Lmt15_Over_UModule2_16 : 32|16@1+ (0.1,0) [0|6553.5] "V"  PC
 SG_ S2P_Lmt15_Over_RModule2_16 : 48|16@1+ (0.1,0) [0|6553.5] "V"  PC

BO_ 2418077265 S2P_Lmt15__17: 8 SBMU
 SG_ S2P_Lmt15_Over_UModule1_17 : 0|16@1+ (0.1,0) [0|6553.5] "V"  PC
 SG_ S2P_Lmt15_Over_RModule1_17 : 16|16@1+ (0.1,0) [0|6553.5] "V"  PC
 SG_ S2P_Lmt15_Over_UModule2_17 : 32|16@1+ (0.1,0) [0|6553.5] "V"  PC
 SG_ S2P_Lmt15_Over_RModule2_17 : 48|16@1+ (0.1,0) [0|6553.5] "V"  PC

BO_ 2418077266 S2P_Lmt15__18: 8 SBMU
 SG_ S2P_Lmt15_Over_UModule1_18 : 0|16@1+ (0.1,0) [0|6553.5] "V"  PC
 SG_ S2P_Lmt15_Over_RModule1_18 : 16|16@1+ (0.1,0) [0|6553.5] "V"  PC
 SG_ S2P_Lmt15_Over_UModule2_18 : 32|16@1+ (0.1,0) [0|6553.5] "V"  PC
 SG_ S2P_Lmt15_Over_RModule2_18 : 48|16@1+ (0.1,0) [0|6553.5] "V"  PC

BO_ 2418077267 S2P_Lmt15__19: 8 SBMU
 SG_ S2P_Lmt15_Over_UModule1_19 : 0|16@1+ (0.1,0) [0|6553.5] "V"  PC
 SG_ S2P_Lmt15_Over_RModule1_19 : 16|16@1+ (0.1,0) [0|6553.5] "V"  PC
 SG_ S2P_Lmt15_Over_UModule2_19 : 32|16@1+ (0.1,0) [0|6553.5] "V"  PC
 SG_ S2P_Lmt15_Over_RModule2_19 : 48|16@1+ (0.1,0) [0|6553.5] "V"  PC

BO_ 2418077268 S2P_Lmt15__20: 8 SBMU
 SG_ S2P_Lmt15_Over_UModule1_20 : 0|16@1+ (0.1,0) [0|6553.5] "V"  PC
 SG_ S2P_Lmt15_Over_RModule1_20 : 16|16@1+ (0.1,0) [0|6553.5] "V"  PC
 SG_ S2P_Lmt15_Over_UModule2_20 : 32|16@1+ (0.1,0) [0|6553.5] "V"  PC
 SG_ S2P_Lmt15_Over_RModule2_20 : 48|16@1+ (0.1,0) [0|6553.5] "V"  PC

BO_ 2418077269 S2P_Lmt15__21: 8 SBMU
 SG_ S2P_Lmt15_Over_UModule1_21 : 0|16@1+ (0.1,0) [0|6553.5] "V"  PC
 SG_ S2P_Lmt15_Over_RModule1_21 : 16|16@1+ (0.1,0) [0|6553.5] "V"  PC
 SG_ S2P_Lmt15_Over_UModule2_21 : 32|16@1+ (0.1,0) [0|6553.5] "V"  PC
 SG_ S2P_Lmt15_Over_RModule2_21 : 48|16@1+ (0.1,0) [0|6553.5] "V"  PC

BO_ 2418077270 S2P_Lmt15__22: 8 SBMU
 SG_ S2P_Lmt15_Over_UModule1_22 : 0|16@1+ (0.1,0) [0|6553.5] "V"  PC
 SG_ S2P_Lmt15_Over_RModule1_22 : 16|16@1+ (0.1,0) [0|6553.5] "V"  PC
 SG_ S2P_Lmt15_Over_UModule2_22 : 32|16@1+ (0.1,0) [0|6553.5] "V"  PC
 SG_ S2P_Lmt15_Over_RModule2_22 : 48|16@1+ (0.1,0) [0|6553.5] "V"  PC

BO_ 2418077271 S2P_Lmt15__23: 8 SBMU
 SG_ S2P_Lmt15_Over_UModule1_23 : 0|16@1+ (0.1,0) [0|6553.5] "V"  PC
 SG_ S2P_Lmt15_Over_RModule1_23 : 16|16@1+ (0.1,0) [0|6553.5] "V"  PC
 SG_ S2P_Lmt15_Over_UModule2_23 : 32|16@1+ (0.1,0) [0|6553.5] "V"  PC
 SG_ S2P_Lmt15_Over_RModule2_23 : 48|16@1+ (0.1,0) [0|6553.5] "V"  PC

BO_ 2418077272 S2P_Lmt15__24: 8 SBMU
 SG_ S2P_Lmt15_Over_UModule1_24 : 0|16@1+ (0.1,0) [0|6553.5] "V"  PC
 SG_ S2P_Lmt15_Over_RModule1_24 : 16|16@1+ (0.1,0) [0|6553.5] "V"  PC
 SG_ S2P_Lmt15_Over_UModule2_24 : 32|16@1+ (0.1,0) [0|6553.5] "V"  PC
 SG_ S2P_Lmt15_Over_RModule2_24 : 48|16@1+ (0.1,0) [0|6553.5] "V"  PC

BO_ 2418077273 S2P_Lmt15__25: 8 SBMU
 SG_ S2P_Lmt15_Over_UModule1_25 : 0|16@1+ (0.1,0) [0|6553.5] "V"  PC
 SG_ S2P_Lmt15_Over_RModule1_25 : 16|16@1+ (0.1,0) [0|6553.5] "V"  PC
 SG_ S2P_Lmt15_Over_UModule2_25 : 32|16@1+ (0.1,0) [0|6553.5] "V"  PC
 SG_ S2P_Lmt15_Over_RModule2_25 : 48|16@1+ (0.1,0) [0|6553.5] "V"  PC

BO_ 2418077274 S2P_Lmt15__26: 8 SBMU
 SG_ S2P_Lmt15_Over_UModule1_26 : 0|16@1+ (0.1,0) [0|6553.5] "V"  PC
 SG_ S2P_Lmt15_Over_RModule1_26 : 16|16@1+ (0.1,0) [0|6553.5] "V"  PC
 SG_ S2P_Lmt15_Over_UModule2_26 : 32|16@1+ (0.1,0) [0|6553.5] "V"  PC
 SG_ S2P_Lmt15_Over_RModule2_26 : 48|16@1+ (0.1,0) [0|6553.5] "V"  PC

BO_ 2418077275 S2P_Lmt15__27: 8 SBMU
 SG_ S2P_Lmt15_Over_UModule1_27 : 0|16@1+ (0.1,0) [0|6553.5] "V"  PC
 SG_ S2P_Lmt15_Over_RModule1_27 : 16|16@1+ (0.1,0) [0|6553.5] "V"  PC
 SG_ S2P_Lmt15_Over_UModule2_27 : 32|16@1+ (0.1,0) [0|6553.5] "V"  PC
 SG_ S2P_Lmt15_Over_RModule2_27 : 48|16@1+ (0.1,0) [0|6553.5] "V"  PC

BO_ 2418077276 S2P_Lmt15__28: 8 SBMU
 SG_ S2P_Lmt15_Over_UModule1_28 : 0|16@1+ (0.1,0) [0|6553.5] "V"  PC
 SG_ S2P_Lmt15_Over_RModule1_28 : 16|16@1+ (0.1,0) [0|6553.5] "V"  PC
 SG_ S2P_Lmt15_Over_UModule2_28 : 32|16@1+ (0.1,0) [0|6553.5] "V"  PC
 SG_ S2P_Lmt15_Over_RModule2_28 : 48|16@1+ (0.1,0) [0|6553.5] "V"  PC

BO_ 2418077277 S2P_Lmt15__29: 8 SBMU
 SG_ S2P_Lmt15_Over_UModule1_29 : 0|16@1+ (0.1,0) [0|6553.5] "V"  PC
 SG_ S2P_Lmt15_Over_RModule1_29 : 16|16@1+ (0.1,0) [0|6553.5] "V"  PC
 SG_ S2P_Lmt15_Over_UModule2_29 : 32|16@1+ (0.1,0) [0|6553.5] "V"  PC
 SG_ S2P_Lmt15_Over_RModule2_29 : 48|16@1+ (0.1,0) [0|6553.5] "V"  PC

BO_ 2418077278 S2P_Lmt15__30: 8 SBMU
 SG_ S2P_Lmt15_Over_UModule1_30 : 0|16@1+ (0.1,0) [0|6553.5] "V"  PC
 SG_ S2P_Lmt15_Over_RModule1_30 : 16|16@1+ (0.1,0) [0|6553.5] "V"  PC
 SG_ S2P_Lmt15_Over_UModule2_30 : 32|16@1+ (0.1,0) [0|6553.5] "V"  PC
 SG_ S2P_Lmt15_Over_RModule2_30 : 48|16@1+ (0.1,0) [0|6553.5] "V"  PC

BO_ 2418077279 S2P_Lmt15__31: 8 SBMU
 SG_ S2P_Lmt15_Over_UModule1_31 : 0|16@1+ (0.1,0) [0|6553.5] "V"  PC
 SG_ S2P_Lmt15_Over_RModule1_31 : 16|16@1+ (0.1,0) [0|6553.5] "V"  PC
 SG_ S2P_Lmt15_Over_UModule2_31 : 32|16@1+ (0.1,0) [0|6553.5] "V"  PC
 SG_ S2P_Lmt15_Over_RModule2_31 : 48|16@1+ (0.1,0) [0|6553.5] "V"  PC

BO_ 2418077280 S2P_Lmt15__32: 8 SBMU
 SG_ S2P_Lmt15_Over_UModule1_32 : 0|16@1+ (0.1,0) [0|6553.5] "V"  PC
 SG_ S2P_Lmt15_Over_RModule1_32 : 16|16@1+ (0.1,0) [0|6553.5] "V"  PC
 SG_ S2P_Lmt15_Over_UModule2_32 : 32|16@1+ (0.1,0) [0|6553.5] "V"  PC
 SG_ S2P_Lmt15_Over_RModule2_32 : 48|16@1+ (0.1,0) [0|6553.5] "V"  PC

BO_ 2418077281 S2P_Lmt15__33: 8 SBMU
 SG_ S2P_Lmt15_Over_UModule1_33 : 0|16@1+ (0.1,0) [0|6553.5] "V"  PC
 SG_ S2P_Lmt15_Over_RModule1_33 : 16|16@1+ (0.1,0) [0|6553.5] "V"  PC
 SG_ S2P_Lmt15_Over_UModule2_33 : 32|16@1+ (0.1,0) [0|6553.5] "V"  PC
 SG_ S2P_Lmt15_Over_RModule2_33 : 48|16@1+ (0.1,0) [0|6553.5] "V"  PC

BO_ 2418077282 S2P_Lmt15__34: 8 SBMU
 SG_ S2P_Lmt15_Over_UModule1_34 : 0|16@1+ (0.1,0) [0|6553.5] "V"  PC
 SG_ S2P_Lmt15_Over_RModule1_34 : 16|16@1+ (0.1,0) [0|6553.5] "V"  PC
 SG_ S2P_Lmt15_Over_UModule2_34 : 32|16@1+ (0.1,0) [0|6553.5] "V"  PC
 SG_ S2P_Lmt15_Over_RModule2_34 : 48|16@1+ (0.1,0) [0|6553.5] "V"  PC

BO_ 2418077283 S2P_Lmt15__35: 8 SBMU
 SG_ S2P_Lmt15_Over_UModule1_35 : 0|16@1+ (0.1,0) [0|6553.5] "V"  PC
 SG_ S2P_Lmt15_Over_RModule1_35 : 16|16@1+ (0.1,0) [0|6553.5] "V"  PC
 SG_ S2P_Lmt15_Over_UModule2_35 : 32|16@1+ (0.1,0) [0|6553.5] "V"  PC
 SG_ S2P_Lmt15_Over_RModule2_35 : 48|16@1+ (0.1,0) [0|6553.5] "V"  PC

BO_ 2418077284 S2P_Lmt15__36: 8 SBMU
 SG_ S2P_Lmt15_Over_UModule1_36 : 0|16@1+ (0.1,0) [0|6553.5] "V"  PC
 SG_ S2P_Lmt15_Over_RModule1_36 : 16|16@1+ (0.1,0) [0|6553.5] "V"  PC
 SG_ S2P_Lmt15_Over_UModule2_36 : 32|16@1+ (0.1,0) [0|6553.5] "V"  PC
 SG_ S2P_Lmt15_Over_RModule2_36 : 48|16@1+ (0.1,0) [0|6553.5] "V"  PC

BO_ 2418077285 S2P_Lmt15__37: 8 SBMU
 SG_ S2P_Lmt15_Over_UModule1_37 : 0|16@1+ (0.1,0) [0|6553.5] "V"  PC
 SG_ S2P_Lmt15_Over_RModule1_37 : 16|16@1+ (0.1,0) [0|6553.5] "V"  PC
 SG_ S2P_Lmt15_Over_UModule2_37 : 32|16@1+ (0.1,0) [0|6553.5] "V"  PC
 SG_ S2P_Lmt15_Over_RModule2_37 : 48|16@1+ (0.1,0) [0|6553.5] "V"  PC

BO_ 2418077286 S2P_Lmt15__38: 8 SBMU
 SG_ S2P_Lmt15_Over_UModule1_38 : 0|16@1+ (0.1,0) [0|6553.5] "V"  PC
 SG_ S2P_Lmt15_Over_RModule1_38 : 16|16@1+ (0.1,0) [0|6553.5] "V"  PC
 SG_ S2P_Lmt15_Over_UModule2_38 : 32|16@1+ (0.1,0) [0|6553.5] "V"  PC
 SG_ S2P_Lmt15_Over_RModule2_38 : 48|16@1+ (0.1,0) [0|6553.5] "V"  PC

BO_ 2418077287 S2P_Lmt15__39: 8 SBMU
 SG_ S2P_Lmt15_Over_UModule1_39 : 0|16@1+ (0.1,0) [0|6553.5] "V"  PC
 SG_ S2P_Lmt15_Over_RModule1_39 : 16|16@1+ (0.1,0) [0|6553.5] "V"  PC
 SG_ S2P_Lmt15_Over_UModule2_39 : 32|16@1+ (0.1,0) [0|6553.5] "V"  PC
 SG_ S2P_Lmt15_Over_RModule2_39 : 48|16@1+ (0.1,0) [0|6553.5] "V"  PC

BO_ 2418077288 S2P_Lmt15__40: 8 SBMU
 SG_ S2P_Lmt15_Over_UModule1_40 : 0|16@1+ (0.1,0) [0|6553.5] "V"  PC
 SG_ S2P_Lmt15_Over_RModule1_40 : 16|16@1+ (0.1,0) [0|6553.5] "V"  PC
 SG_ S2P_Lmt15_Over_UModule2_40 : 32|16@1+ (0.1,0) [0|6553.5] "V"  PC
 SG_ S2P_Lmt15_Over_RModule2_40 : 48|16@1+ (0.1,0) [0|6553.5] "V"  PC

BO_ 2418077289 S2P_Lmt15__41: 8 SBMU
 SG_ S2P_Lmt15_Over_UModule1_41 : 0|16@1+ (0.1,0) [0|6553.5] "V"  PC
 SG_ S2P_Lmt15_Over_RModule1_41 : 16|16@1+ (0.1,0) [0|6553.5] "V"  PC
 SG_ S2P_Lmt15_Over_UModule2_41 : 32|16@1+ (0.1,0) [0|6553.5] "V"  PC
 SG_ S2P_Lmt15_Over_RModule2_41 : 48|16@1+ (0.1,0) [0|6553.5] "V"  PC

BO_ 2418077290 S2P_Lmt15__42: 8 SBMU
 SG_ S2P_Lmt15_Over_UModule1_42 : 0|16@1+ (0.1,0) [0|6553.5] "V"  PC
 SG_ S2P_Lmt15_Over_RModule1_42 : 16|16@1+ (0.1,0) [0|6553.5] "V"  PC
 SG_ S2P_Lmt15_Over_UModule2_42 : 32|16@1+ (0.1,0) [0|6553.5] "V"  PC
 SG_ S2P_Lmt15_Over_RModule2_42 : 48|16@1+ (0.1,0) [0|6553.5] "V"  PC

BO_ 2418077291 S2P_Lmt15__43: 8 SBMU
 SG_ S2P_Lmt15_Over_UModule1_43 : 0|16@1+ (0.1,0) [0|6553.5] "V"  PC
 SG_ S2P_Lmt15_Over_RModule1_43 : 16|16@1+ (0.1,0) [0|6553.5] "V"  PC
 SG_ S2P_Lmt15_Over_UModule2_43 : 32|16@1+ (0.1,0) [0|6553.5] "V"  PC
 SG_ S2P_Lmt15_Over_RModule2_43 : 48|16@1+ (0.1,0) [0|6553.5] "V"  PC

BO_ 2418077292 S2P_Lmt15__44: 8 SBMU
 SG_ S2P_Lmt15_Over_UModule1_44 : 0|16@1+ (0.1,0) [0|6553.5] "V"  PC
 SG_ S2P_Lmt15_Over_RModule1_44 : 16|16@1+ (0.1,0) [0|6553.5] "V"  PC
 SG_ S2P_Lmt15_Over_UModule2_44 : 32|16@1+ (0.1,0) [0|6553.5] "V"  PC
 SG_ S2P_Lmt15_Over_RModule2_44 : 48|16@1+ (0.1,0) [0|6553.5] "V"  PC

BO_ 2418077293 S2P_Lmt15__45: 8 SBMU
 SG_ S2P_Lmt15_Over_UModule1_45 : 0|16@1+ (0.1,0) [0|6553.5] "V"  PC
 SG_ S2P_Lmt15_Over_RModule1_45 : 16|16@1+ (0.1,0) [0|6553.5] "V"  PC
 SG_ S2P_Lmt15_Over_UModule2_45 : 32|16@1+ (0.1,0) [0|6553.5] "V"  PC
 SG_ S2P_Lmt15_Over_RModule2_45 : 48|16@1+ (0.1,0) [0|6553.5] "V"  PC

BO_ 2418077294 S2P_Lmt15__46: 8 SBMU
 SG_ S2P_Lmt15_Over_UModule1_46 : 0|16@1+ (0.1,0) [0|6553.5] "V"  PC
 SG_ S2P_Lmt15_Over_RModule1_46 : 16|16@1+ (0.1,0) [0|6553.5] "V"  PC
 SG_ S2P_Lmt15_Over_UModule2_46 : 32|16@1+ (0.1,0) [0|6553.5] "V"  PC
 SG_ S2P_Lmt15_Over_RModule2_46 : 48|16@1+ (0.1,0) [0|6553.5] "V"  PC

BO_ 2418077295 S2P_Lmt15__47: 8 SBMU
 SG_ S2P_Lmt15_Over_UModule1_47 : 0|16@1+ (0.1,0) [0|6553.5] "V"  PC
 SG_ S2P_Lmt15_Over_RModule1_47 : 16|16@1+ (0.1,0) [0|6553.5] "V"  PC
 SG_ S2P_Lmt15_Over_UModule2_47 : 32|16@1+ (0.1,0) [0|6553.5] "V"  PC
 SG_ S2P_Lmt15_Over_RModule2_47 : 48|16@1+ (0.1,0) [0|6553.5] "V"  PC

BO_ 2418077296 S2P_Lmt15__48: 8 SBMU
 SG_ S2P_Lmt15_Over_UModule1_48 : 0|16@1+ (0.1,0) [0|6553.5] "V"  PC
 SG_ S2P_Lmt15_Over_RModule1_48 : 16|16@1+ (0.1,0) [0|6553.5] "V"  PC
 SG_ S2P_Lmt15_Over_UModule2_48 : 32|16@1+ (0.1,0) [0|6553.5] "V"  PC
 SG_ S2P_Lmt15_Over_RModule2_48 : 48|16@1+ (0.1,0) [0|6553.5] "V"  PC

BO_ 2418077297 S2P_Lmt15__49: 8 SBMU
 SG_ S2P_Lmt15_Over_UModule1_49 : 0|16@1+ (0.1,0) [0|6553.5] "V"  PC
 SG_ S2P_Lmt15_Over_RModule1_49 : 16|16@1+ (0.1,0) [0|6553.5] "V"  PC
 SG_ S2P_Lmt15_Over_UModule2_49 : 32|16@1+ (0.1,0) [0|6553.5] "V"  PC
 SG_ S2P_Lmt15_Over_RModule2_49 : 48|16@1+ (0.1,0) [0|6553.5] "V"  PC

BO_ 2418077298 S2P_Lmt15__50: 8 SBMU
 SG_ S2P_Lmt15_Over_UModule1_50 : 0|16@1+ (0.1,0) [0|6553.5] "V"  PC
 SG_ S2P_Lmt15_Over_RModule1_50 : 16|16@1+ (0.1,0) [0|6553.5] "V"  PC
 SG_ S2P_Lmt15_Over_UModule2_50 : 32|16@1+ (0.1,0) [0|6553.5] "V"  PC
 SG_ S2P_Lmt15_Over_RModule2_50 : 48|16@1+ (0.1,0) [0|6553.5] "V"  PC

BO_ 2418077299 S2P_Lmt15__51: 8 SBMU
 SG_ S2P_Lmt15_Over_UModule1_51 : 0|16@1+ (0.1,0) [0|6553.5] "V"  PC
 SG_ S2P_Lmt15_Over_RModule1_51 : 16|16@1+ (0.1,0) [0|6553.5] "V"  PC
 SG_ S2P_Lmt15_Over_UModule2_51 : 32|16@1+ (0.1,0) [0|6553.5] "V"  PC
 SG_ S2P_Lmt15_Over_RModule2_51 : 48|16@1+ (0.1,0) [0|6553.5] "V"  PC

BO_ 2418077300 S2P_Lmt15__52: 8 SBMU
 SG_ S2P_Lmt15_Over_UModule1_52 : 0|16@1+ (0.1,0) [0|6553.5] "V"  PC
 SG_ S2P_Lmt15_Over_RModule1_52 : 16|16@1+ (0.1,0) [0|6553.5] "V"  PC
 SG_ S2P_Lmt15_Over_UModule2_52 : 32|16@1+ (0.1,0) [0|6553.5] "V"  PC
 SG_ S2P_Lmt15_Over_RModule2_52 : 48|16@1+ (0.1,0) [0|6553.5] "V"  PC

BO_ 2418077301 S2P_Lmt15__53: 8 SBMU
 SG_ S2P_Lmt15_Over_UModule1_53 : 0|16@1+ (0.1,0) [0|6553.5] "V"  PC
 SG_ S2P_Lmt15_Over_RModule1_53 : 16|16@1+ (0.1,0) [0|6553.5] "V"  PC
 SG_ S2P_Lmt15_Over_UModule2_53 : 32|16@1+ (0.1,0) [0|6553.5] "V"  PC
 SG_ S2P_Lmt15_Over_RModule2_53 : 48|16@1+ (0.1,0) [0|6553.5] "V"  PC

BO_ 2418077302 S2P_Lmt15__54: 8 SBMU
 SG_ S2P_Lmt15_Over_UModule1_54 : 0|16@1+ (0.1,0) [0|6553.5] "V"  PC
 SG_ S2P_Lmt15_Over_RModule1_54 : 16|16@1+ (0.1,0) [0|6553.5] "V"  PC
 SG_ S2P_Lmt15_Over_UModule2_54 : 32|16@1+ (0.1,0) [0|6553.5] "V"  PC
 SG_ S2P_Lmt15_Over_RModule2_54 : 48|16@1+ (0.1,0) [0|6553.5] "V"  PC

BO_ 2418077303 S2P_Lmt15__55: 8 SBMU
 SG_ S2P_Lmt15_Over_UModule1_55 : 0|16@1+ (0.1,0) [0|6553.5] "V"  PC
 SG_ S2P_Lmt15_Over_RModule1_55 : 16|16@1+ (0.1,0) [0|6553.5] "V"  PC
 SG_ S2P_Lmt15_Over_UModule2_55 : 32|16@1+ (0.1,0) [0|6553.5] "V"  PC
 SG_ S2P_Lmt15_Over_RModule2_55 : 48|16@1+ (0.1,0) [0|6553.5] "V"  PC

BO_ 2418077304 S2P_Lmt15__56: 8 SBMU
 SG_ S2P_Lmt15_Over_UModule1_56 : 0|16@1+ (0.1,0) [0|6553.5] "V"  PC
 SG_ S2P_Lmt15_Over_RModule1_56 : 16|16@1+ (0.1,0) [0|6553.5] "V"  PC
 SG_ S2P_Lmt15_Over_UModule2_56 : 32|16@1+ (0.1,0) [0|6553.5] "V"  PC
 SG_ S2P_Lmt15_Over_RModule2_56 : 48|16@1+ (0.1,0) [0|6553.5] "V"  PC

BO_ 2418077305 S2P_Lmt15__57: 8 SBMU
 SG_ S2P_Lmt15_Over_UModule1_57 : 0|16@1+ (0.1,0) [0|6553.5] "V"  PC
 SG_ S2P_Lmt15_Over_RModule1_57 : 16|16@1+ (0.1,0) [0|6553.5] "V"  PC
 SG_ S2P_Lmt15_Over_UModule2_57 : 32|16@1+ (0.1,0) [0|6553.5] "V"  PC
 SG_ S2P_Lmt15_Over_RModule2_57 : 48|16@1+ (0.1,0) [0|6553.5] "V"  PC

BO_ 2418077306 S2P_Lmt15__58: 8 SBMU
 SG_ S2P_Lmt15_Over_UModule1_58 : 0|16@1+ (0.1,0) [0|6553.5] "V"  PC
 SG_ S2P_Lmt15_Over_RModule1_58 : 16|16@1+ (0.1,0) [0|6553.5] "V"  PC
 SG_ S2P_Lmt15_Over_UModule2_58 : 32|16@1+ (0.1,0) [0|6553.5] "V"  PC
 SG_ S2P_Lmt15_Over_RModule2_58 : 48|16@1+ (0.1,0) [0|6553.5] "V"  PC

BO_ 2418077307 S2P_Lmt15__59: 8 SBMU
 SG_ S2P_Lmt15_Over_UModule1_59 : 0|16@1+ (0.1,0) [0|6553.5] "V"  PC
 SG_ S2P_Lmt15_Over_RModule1_59 : 16|16@1+ (0.1,0) [0|6553.5] "V"  PC
 SG_ S2P_Lmt15_Over_UModule2_59 : 32|16@1+ (0.1,0) [0|6553.5] "V"  PC
 SG_ S2P_Lmt15_Over_RModule2_59 : 48|16@1+ (0.1,0) [0|6553.5] "V"  PC

CM_ SG_ 2332683949 M2P_SysMaxTemp_HvOn29 "系统所有高压在线的电柜的最大电芯温度";
CM_ SG_ 2332683949 M2P_SysMinTemp_HvOn29 "系统所有高压在线的电柜的最小电芯温度";
CM_ SG_ 2332683949 M2P_SysAvgTemp_HvOn29 "系统所有高压在线的电柜的平均电芯温度";
CM_ SG_ 2332683949 M2P_SbmuPst_SysMaxTemp_HvOn29 "系统所有高压在线的电柜的最大电芯温度所处SBMU编号";
CM_ SG_ 2332683949 M2P_CscPst_SysMaxTemp_HvOn29 "系统所有高压在线的电柜的最大电芯温度所处CSC编号";
CM_ SG_ 2332683949 M2P_SbmuPst_SysMinTemp_HvOn29 "系统所有高压在线的电柜的最小电芯温度所处SBMU编号";
CM_ SG_ 2332683949 M2P_CscPst_SysMinTemp_HvOn29 "系统所有高压在线的电柜的最小电芯温度所处CSC编号";
CM_ SG_ 2332683950 M2P_SysMaxTemp_HvOn30 "系统所有高压在线的电柜的最大电芯温度";
CM_ SG_ 2332683950 M2P_SysMinTemp_HvOn30 "系统所有高压在线的电柜的最小电芯温度";
CM_ SG_ 2332683950 M2P_SysAvgTemp_HvOn30 "系统所有高压在线的电柜的平均电芯温度";
CM_ SG_ 2332683950 M2P_SbmuPst_SysMaxTemp_HvOn30 "系统所有高压在线的电柜的最大电芯温度所处SBMU编号";
CM_ SG_ 2332683950 M2P_CscPst_SysMaxTemp_HvOn30 "系统所有高压在线的电柜的最大电芯温度所处CSC编号";
CM_ SG_ 2332683950 M2P_SbmuPst_SysMinTemp_HvOn30 "系统所有高压在线的电柜的最小电芯温度所处SBMU编号";
CM_ SG_ 2332683950 M2P_CscPst_SysMinTemp_HvOn30 "系统所有高压在线的电柜的最小电芯温度所处CSC编号";
CM_ SG_ 2332683951 M2P_SysMaxTemp_HvOn31 "系统所有高压在线的电柜的最大电芯温度";
CM_ SG_ 2332683951 M2P_SysMinTemp_HvOn31 "系统所有高压在线的电柜的最小电芯温度";
CM_ SG_ 2332683951 M2P_SysAvgTemp_HvOn31 "系统所有高压在线的电柜的平均电芯温度";
CM_ SG_ 2332683951 M2P_SbmuPst_SysMaxTemp_HvOn31 "系统所有高压在线的电柜的最大电芯温度所处SBMU编号";
CM_ SG_ 2332683951 M2P_CscPst_SysMaxTemp_HvOn31 "系统所有高压在线的电柜的最大电芯温度所处CSC编号";
CM_ SG_ 2332683951 M2P_SbmuPst_SysMinTemp_HvOn31 "系统所有高压在线的电柜的最小电芯温度所处SBMU编号";
CM_ SG_ 2332683951 M2P_CscPst_SysMinTemp_HvOn31 "系统所有高压在线的电柜的最小电芯温度所处CSC编号";
CM_ SG_ 2332749457 M2P_SbmuPst_SysMaxVolt_HvOn01 "系统所有高压在线的电柜的最大电芯电压所处SBMU编号";
CM_ SG_ 2332749457 M2P_CscPst_SysMaxVolt_HvOn01 "系统所有高压在线的电柜的最大电芯电压所处CSC编号";
CM_ SG_ 2332749457 M2P_CellPst_SysMaxVolt_HvOn01 "系统所有高压在线的电柜的最大电芯电压所处Cell编号";
CM_ SG_ 2332749457 M2P_SbmuPst_SysMinVolt_HvOn01 "系统所有高压在线的电柜的最小电芯电压所处SBMU编号";
CM_ SG_ 2332749457 M2P_CscPst_SysMinVolt_HvOn01 "系统所有高压在线的电柜的最小电芯电压所处CSC编号";
CM_ SG_ 2332749457 M2P_CellPst_SysMinVolt_HvOn01 "系统所有高压在线的电柜的最小电芯电压所处Cell编号";
CM_ SG_ 2332749457 M2P_SbmuPst_SysMaxTemp_LvOn01 "系统所有低压在线的电柜的最大电芯温度所处SBMU编号";
CM_ SG_ 2332749457 M2P_CscPst_SysMaxTemp_LvOn01 "系统所有低压在线的电柜的最大电芯温度所处CSC编号";
CM_ SG_ 2332749458 M2P_SbmuPst_SysMaxVolt_HvOn02 "系统所有高压在线的电柜的最大电芯电压所处SBMU编号";
CM_ SG_ 2332749458 M2P_CscPst_SysMaxVolt_HvOn02 "系统所有高压在线的电柜的最大电芯电压所处CSC编号";
CM_ SG_ 2332749458 M2P_CellPst_SysMaxVolt_HvOn02 "系统所有高压在线的电柜的最大电芯电压所处Cell编号";
CM_ SG_ 2332749458 M2P_SbmuPst_SysMinVolt_HvOn02 "系统所有高压在线的电柜的最小电芯电压所处SBMU编号";
CM_ SG_ 2332749458 M2P_CscPst_SysMinVolt_HvOn02 "系统所有高压在线的电柜的最小电芯电压所处CSC编号";
CM_ SG_ 2332749458 M2P_CellPst_SysMinVolt_HvOn02 "系统所有高压在线的电柜的最小电芯电压所处Cell编号";
CM_ SG_ 2332749458 M2P_SbmuPst_SysMaxTemp_LvOn02 "系统所有低压在线的电柜的最大电芯温度所处SBMU编号";
CM_ SG_ 2332749458 M2P_CscPst_SysMaxTemp_LvOn02 "系统所有低压在线的电柜的最大电芯温度所处CSC编号";
CM_ SG_ 2332749459 M2P_SbmuPst_SysMaxVolt_HvOn03 "系统所有高压在线的电柜的最大电芯电压所处SBMU编号";
CM_ SG_ 2332749459 M2P_CscPst_SysMaxVolt_HvOn03 "系统所有高压在线的电柜的最大电芯电压所处CSC编号";
CM_ SG_ 2332749459 M2P_CellPst_SysMaxVolt_HvOn03 "系统所有高压在线的电柜的最大电芯电压所处Cell编号";
CM_ SG_ 2332749459 M2P_SbmuPst_SysMinVolt_HvOn03 "系统所有高压在线的电柜的最小电芯电压所处SBMU编号";
CM_ SG_ 2332749459 M2P_CscPst_SysMinVolt_HvOn03 "系统所有高压在线的电柜的最小电芯电压所处CSC编号";
CM_ SG_ 2332749459 M2P_CellPst_SysMinVolt_HvOn03 "系统所有高压在线的电柜的最小电芯电压所处Cell编号";
CM_ SG_ 2332749459 M2P_SbmuPst_SysMaxTemp_LvOn03 "系统所有低压在线的电柜的最大电芯温度所处SBMU编号";
CM_ SG_ 2332749459 M2P_CscPst_SysMaxTemp_LvOn03 "系统所有低压在线的电柜的最大电芯温度所处CSC编号";
CM_ SG_ 2332749460 M2P_SbmuPst_SysMaxVolt_HvOn04 "系统所有高压在线的电柜的最大电芯电压所处SBMU编号";
CM_ SG_ 2332749460 M2P_CscPst_SysMaxVolt_HvOn04 "系统所有高压在线的电柜的最大电芯电压所处CSC编号";
CM_ SG_ 2332749460 M2P_CellPst_SysMaxVolt_HvOn04 "系统所有高压在线的电柜的最大电芯电压所处Cell编号";
CM_ SG_ 2332749460 M2P_SbmuPst_SysMinVolt_HvOn04 "系统所有高压在线的电柜的最小电芯电压所处SBMU编号";
CM_ SG_ 2332749460 M2P_CscPst_SysMinVolt_HvOn04 "系统所有高压在线的电柜的最小电芯电压所处CSC编号";
CM_ SG_ 2332749460 M2P_CellPst_SysMinVolt_HvOn04 "系统所有高压在线的电柜的最小电芯电压所处Cell编号";
CM_ SG_ 2332749460 M2P_SbmuPst_SysMaxTemp_LvOn04 "系统所有低压在线的电柜的最大电芯温度所处SBMU编号";
CM_ SG_ 2332749460 M2P_CscPst_SysMaxTemp_LvOn04 "系统所有低压在线的电柜的最大电芯温度所处CSC编号";
CM_ SG_ 2332749461 M2P_SbmuPst_SysMaxVolt_HvOn05 "系统所有高压在线的电柜的最大电芯电压所处SBMU编号";
CM_ SG_ 2332749461 M2P_CscPst_SysMaxVolt_HvOn05 "系统所有高压在线的电柜的最大电芯电压所处CSC编号";
CM_ SG_ 2332749461 M2P_CellPst_SysMaxVolt_HvOn05 "系统所有高压在线的电柜的最大电芯电压所处Cell编号";
CM_ SG_ 2332749461 M2P_SbmuPst_SysMinVolt_HvOn05 "系统所有高压在线的电柜的最小电芯电压所处SBMU编号";
CM_ SG_ 2332749461 M2P_CscPst_SysMinVolt_HvOn05 "系统所有高压在线的电柜的最小电芯电压所处CSC编号";
CM_ SG_ 2332749461 M2P_CellPst_SysMinVolt_HvOn05 "系统所有高压在线的电柜的最小电芯电压所处Cell编号";
CM_ SG_ 2332749461 M2P_SbmuPst_SysMaxTemp_LvOn05 "系统所有低压在线的电柜的最大电芯温度所处SBMU编号";
CM_ SG_ 2332749461 M2P_CscPst_SysMaxTemp_LvOn05 "系统所有低压在线的电柜的最大电芯温度所处CSC编号";
CM_ SG_ 2332749462 M2P_SbmuPst_SysMaxVolt_HvOn06 "系统所有高压在线的电柜的最大电芯电压所处SBMU编号";
CM_ SG_ 2332749462 M2P_CscPst_SysMaxVolt_HvOn06 "系统所有高压在线的电柜的最大电芯电压所处CSC编号";
CM_ SG_ 2332749462 M2P_CellPst_SysMaxVolt_HvOn06 "系统所有高压在线的电柜的最大电芯电压所处Cell编号";
CM_ SG_ 2332749462 M2P_SbmuPst_SysMinVolt_HvOn06 "系统所有高压在线的电柜的最小电芯电压所处SBMU编号";
CM_ SG_ 2332749462 M2P_CscPst_SysMinVolt_HvOn06 "系统所有高压在线的电柜的最小电芯电压所处CSC编号";
CM_ SG_ 2332749462 M2P_CellPst_SysMinVolt_HvOn06 "系统所有高压在线的电柜的最小电芯电压所处Cell编号";
CM_ SG_ 2332749462 M2P_SbmuPst_SysMaxTemp_LvOn06 "系统所有低压在线的电柜的最大电芯温度所处SBMU编号";
CM_ SG_ 2332749462 M2P_CscPst_SysMaxTemp_LvOn06 "系统所有低压在线的电柜的最大电芯温度所处CSC编号";
CM_ SG_ 2332749463 M2P_SbmuPst_SysMaxVolt_HvOn07 "系统所有高压在线的电柜的最大电芯电压所处SBMU编号";
CM_ SG_ 2332749463 M2P_CscPst_SysMaxVolt_HvOn07 "系统所有高压在线的电柜的最大电芯电压所处CSC编号";
CM_ SG_ 2332749463 M2P_CellPst_SysMaxVolt_HvOn07 "系统所有高压在线的电柜的最大电芯电压所处Cell编号";
CM_ SG_ 2332749463 M2P_SbmuPst_SysMinVolt_HvOn07 "系统所有高压在线的电柜的最小电芯电压所处SBMU编号";
CM_ SG_ 2332749463 M2P_CscPst_SysMinVolt_HvOn07 "系统所有高压在线的电柜的最小电芯电压所处CSC编号";
CM_ SG_ 2332749463 M2P_CellPst_SysMinVolt_HvOn07 "系统所有高压在线的电柜的最小电芯电压所处Cell编号";
CM_ SG_ 2332749463 M2P_SbmuPst_SysMaxTemp_LvOn07 "系统所有低压在线的电柜的最大电芯温度所处SBMU编号";
CM_ SG_ 2332749463 M2P_CscPst_SysMaxTemp_LvOn07 "系统所有低压在线的电柜的最大电芯温度所处CSC编号";
CM_ SG_ 2332749464 M2P_SbmuPst_SysMaxVolt_HvOn08 "系统所有高压在线的电柜的最大电芯电压所处SBMU编号";
CM_ SG_ 2332749464 M2P_CscPst_SysMaxVolt_HvOn08 "系统所有高压在线的电柜的最大电芯电压所处CSC编号";
CM_ SG_ 2332749464 M2P_CellPst_SysMaxVolt_HvOn08 "系统所有高压在线的电柜的最大电芯电压所处Cell编号";
CM_ SG_ 2332749464 M2P_SbmuPst_SysMinVolt_HvOn08 "系统所有高压在线的电柜的最小电芯电压所处SBMU编号";
CM_ SG_ 2332749464 M2P_CscPst_SysMinVolt_HvOn08 "系统所有高压在线的电柜的最小电芯电压所处CSC编号";
CM_ SG_ 2332749464 M2P_CellPst_SysMinVolt_HvOn08 "系统所有高压在线的电柜的最小电芯电压所处Cell编号";
CM_ SG_ 2332749464 M2P_SbmuPst_SysMaxTemp_LvOn08 "系统所有低压在线的电柜的最大电芯温度所处SBMU编号";
CM_ SG_ 2332749464 M2P_CscPst_SysMaxTemp_LvOn08 "系统所有低压在线的电柜的最大电芯温度所处CSC编号";
CM_ SG_ 2332749465 M2P_SbmuPst_SysMaxVolt_HvOn09 "系统所有高压在线的电柜的最大电芯电压所处SBMU编号";
CM_ SG_ 2332749465 M2P_CscPst_SysMaxVolt_HvOn09 "系统所有高压在线的电柜的最大电芯电压所处CSC编号";
CM_ SG_ 2332749465 M2P_CellPst_SysMaxVolt_HvOn09 "系统所有高压在线的电柜的最大电芯电压所处Cell编号";
CM_ SG_ 2332749465 M2P_SbmuPst_SysMinVolt_HvOn09 "系统所有高压在线的电柜的最小电芯电压所处SBMU编号";
CM_ SG_ 2332749465 M2P_CscPst_SysMinVolt_HvOn09 "系统所有高压在线的电柜的最小电芯电压所处CSC编号";
CM_ SG_ 2332749465 M2P_CellPst_SysMinVolt_HvOn09 "系统所有高压在线的电柜的最小电芯电压所处Cell编号";
CM_ SG_ 2332749465 M2P_SbmuPst_SysMaxTemp_LvOn09 "系统所有低压在线的电柜的最大电芯温度所处SBMU编号";
CM_ SG_ 2332749465 M2P_CscPst_SysMaxTemp_LvOn09 "系统所有低压在线的电柜的最大电芯温度所处CSC编号";
CM_ SG_ 2332749466 M2P_SbmuPst_SysMaxVolt_HvOn10 "系统所有高压在线的电柜的最大电芯电压所处SBMU编号";
CM_ SG_ 2332749466 M2P_CscPst_SysMaxVolt_HvOn10 "系统所有高压在线的电柜的最大电芯电压所处CSC编号";
CM_ SG_ 2332749466 M2P_CellPst_SysMaxVolt_HvOn10 "系统所有高压在线的电柜的最大电芯电压所处Cell编号";
CM_ SG_ 2332749466 M2P_SbmuPst_SysMinVolt_HvOn10 "系统所有高压在线的电柜的最小电芯电压所处SBMU编号";
CM_ SG_ 2332749466 M2P_CscPst_SysMinVolt_HvOn10 "系统所有高压在线的电柜的最小电芯电压所处CSC编号";
CM_ SG_ 2332749466 M2P_CellPst_SysMinVolt_HvOn10 "系统所有高压在线的电柜的最小电芯电压所处Cell编号";
CM_ SG_ 2332749466 M2P_SbmuPst_SysMaxTemp_LvOn10 "系统所有低压在线的电柜的最大电芯温度所处SBMU编号";
CM_ SG_ 2332749466 M2P_CscPst_SysMaxTemp_LvOn10 "系统所有低压在线的电柜的最大电芯温度所处CSC编号";
CM_ SG_ 2332749467 M2P_SbmuPst_SysMaxVolt_HvOn11 "系统所有高压在线的电柜的最大电芯电压所处SBMU编号";
CM_ SG_ 2332749467 M2P_CscPst_SysMaxVolt_HvOn11 "系统所有高压在线的电柜的最大电芯电压所处CSC编号";
CM_ SG_ 2332749467 M2P_CellPst_SysMaxVolt_HvOn11 "系统所有高压在线的电柜的最大电芯电压所处Cell编号";
CM_ SG_ 2332749467 M2P_SbmuPst_SysMinVolt_HvOn11 "系统所有高压在线的电柜的最小电芯电压所处SBMU编号";
CM_ SG_ 2332749467 M2P_CscPst_SysMinVolt_HvOn11 "系统所有高压在线的电柜的最小电芯电压所处CSC编号";
CM_ SG_ 2332749467 M2P_CellPst_SysMinVolt_HvOn11 "系统所有高压在线的电柜的最小电芯电压所处Cell编号";
CM_ SG_ 2332749467 M2P_SbmuPst_SysMaxTemp_LvOn11 "系统所有低压在线的电柜的最大电芯温度所处SBMU编号";
CM_ SG_ 2332749467 M2P_CscPst_SysMaxTemp_LvOn11 "系统所有低压在线的电柜的最大电芯温度所处CSC编号";
CM_ SG_ 2332749468 M2P_SbmuPst_SysMaxVolt_HvOn12 "系统所有高压在线的电柜的最大电芯电压所处SBMU编号";
CM_ SG_ 2332749468 M2P_CscPst_SysMaxVolt_HvOn12 "系统所有高压在线的电柜的最大电芯电压所处CSC编号";
CM_ SG_ 2332749468 M2P_CellPst_SysMaxVolt_HvOn12 "系统所有高压在线的电柜的最大电芯电压所处Cell编号";
CM_ SG_ 2332749468 M2P_SbmuPst_SysMinVolt_HvOn12 "系统所有高压在线的电柜的最小电芯电压所处SBMU编号";
CM_ SG_ 2332749468 M2P_CscPst_SysMinVolt_HvOn12 "系统所有高压在线的电柜的最小电芯电压所处CSC编号";
CM_ SG_ 2332749468 M2P_CellPst_SysMinVolt_HvOn12 "系统所有高压在线的电柜的最小电芯电压所处Cell编号";
CM_ SG_ 2332749468 M2P_SbmuPst_SysMaxTemp_LvOn12 "系统所有低压在线的电柜的最大电芯温度所处SBMU编号";
CM_ SG_ 2332749468 M2P_CscPst_SysMaxTemp_LvOn12 "系统所有低压在线的电柜的最大电芯温度所处CSC编号";
CM_ SG_ 2332749469 M2P_SbmuPst_SysMaxVolt_HvOn13 "系统所有高压在线的电柜的最大电芯电压所处SBMU编号";
CM_ SG_ 2332749469 M2P_CscPst_SysMaxVolt_HvOn13 "系统所有高压在线的电柜的最大电芯电压所处CSC编号";
CM_ SG_ 2332749469 M2P_CellPst_SysMaxVolt_HvOn13 "系统所有高压在线的电柜的最大电芯电压所处Cell编号";
CM_ SG_ 2332749469 M2P_SbmuPst_SysMinVolt_HvOn13 "系统所有高压在线的电柜的最小电芯电压所处SBMU编号";
CM_ SG_ 2332749469 M2P_CscPst_SysMinVolt_HvOn13 "系统所有高压在线的电柜的最小电芯电压所处CSC编号";
CM_ SG_ 2332749469 M2P_CellPst_SysMinVolt_HvOn13 "系统所有高压在线的电柜的最小电芯电压所处Cell编号";
CM_ SG_ 2332749469 M2P_SbmuPst_SysMaxTemp_LvOn13 "系统所有低压在线的电柜的最大电芯温度所处SBMU编号";
CM_ SG_ 2332749469 M2P_CscPst_SysMaxTemp_LvOn13 "系统所有低压在线的电柜的最大电芯温度所处CSC编号";
CM_ SG_ 2332749470 M2P_SbmuPst_SysMaxVolt_HvOn14 "系统所有高压在线的电柜的最大电芯电压所处SBMU编号";
CM_ SG_ 2332749470 M2P_CscPst_SysMaxVolt_HvOn14 "系统所有高压在线的电柜的最大电芯电压所处CSC编号";
CM_ SG_ 2332749470 M2P_CellPst_SysMaxVolt_HvOn14 "系统所有高压在线的电柜的最大电芯电压所处Cell编号";
CM_ SG_ 2332749470 M2P_SbmuPst_SysMinVolt_HvOn14 "系统所有高压在线的电柜的最小电芯电压所处SBMU编号";
CM_ SG_ 2332749470 M2P_CscPst_SysMinVolt_HvOn14 "系统所有高压在线的电柜的最小电芯电压所处CSC编号";
CM_ SG_ 2332749470 M2P_CellPst_SysMinVolt_HvOn14 "系统所有高压在线的电柜的最小电芯电压所处Cell编号";
CM_ SG_ 2332749470 M2P_SbmuPst_SysMaxTemp_LvOn14 "系统所有低压在线的电柜的最大电芯温度所处SBMU编号";
CM_ SG_ 2332749470 M2P_CscPst_SysMaxTemp_LvOn14 "系统所有低压在线的电柜的最大电芯温度所处CSC编号";
CM_ SG_ 2332749471 M2P_SbmuPst_SysMaxVolt_HvOn15 "系统所有高压在线的电柜的最大电芯电压所处SBMU编号";
CM_ SG_ 2332749471 M2P_CscPst_SysMaxVolt_HvOn15 "系统所有高压在线的电柜的最大电芯电压所处CSC编号";
CM_ SG_ 2332749471 M2P_CellPst_SysMaxVolt_HvOn15 "系统所有高压在线的电柜的最大电芯电压所处Cell编号";
CM_ SG_ 2332749471 M2P_SbmuPst_SysMinVolt_HvOn15 "系统所有高压在线的电柜的最小电芯电压所处SBMU编号";
CM_ SG_ 2332749471 M2P_CscPst_SysMinVolt_HvOn15 "系统所有高压在线的电柜的最小电芯电压所处CSC编号";
CM_ SG_ 2332749471 M2P_CellPst_SysMinVolt_HvOn15 "系统所有高压在线的电柜的最小电芯电压所处Cell编号";
CM_ SG_ 2332749471 M2P_SbmuPst_SysMaxTemp_LvOn15 "系统所有低压在线的电柜的最大电芯温度所处SBMU编号";
CM_ SG_ 2332749471 M2P_CscPst_SysMaxTemp_LvOn15 "系统所有低压在线的电柜的最大电芯温度所处CSC编号";
CM_ SG_ 2332749472 M2P_SbmuPst_SysMaxVolt_HvOn16 "系统所有高压在线的电柜的最大电芯电压所处SBMU编号";
CM_ SG_ 2332749472 M2P_CscPst_SysMaxVolt_HvOn16 "系统所有高压在线的电柜的最大电芯电压所处CSC编号";
CM_ SG_ 2332749472 M2P_CellPst_SysMaxVolt_HvOn16 "系统所有高压在线的电柜的最大电芯电压所处Cell编号";
CM_ SG_ 2332749472 M2P_SbmuPst_SysMinVolt_HvOn16 "系统所有高压在线的电柜的最小电芯电压所处SBMU编号";
CM_ SG_ 2332749472 M2P_CscPst_SysMinVolt_HvOn16 "系统所有高压在线的电柜的最小电芯电压所处CSC编号";
CM_ SG_ 2332749472 M2P_CellPst_SysMinVolt_HvOn16 "系统所有高压在线的电柜的最小电芯电压所处Cell编号";
CM_ SG_ 2332749472 M2P_SbmuPst_SysMaxTemp_LvOn16 "系统所有低压在线的电柜的最大电芯温度所处SBMU编号";
CM_ SG_ 2332749472 M2P_CscPst_SysMaxTemp_LvOn16 "系统所有低压在线的电柜的最大电芯温度所处CSC编号";
CM_ SG_ 2332749473 M2P_SbmuPst_SysMaxVolt_HvOn17 "系统所有高压在线的电柜的最大电芯电压所处SBMU编号";
CM_ SG_ 2332749473 M2P_CscPst_SysMaxVolt_HvOn17 "系统所有高压在线的电柜的最大电芯电压所处CSC编号";
CM_ SG_ 2332749473 M2P_CellPst_SysMaxVolt_HvOn17 "系统所有高压在线的电柜的最大电芯电压所处Cell编号";
CM_ SG_ 2332749473 M2P_SbmuPst_SysMinVolt_HvOn17 "系统所有高压在线的电柜的最小电芯电压所处SBMU编号";
CM_ SG_ 2332749473 M2P_CscPst_SysMinVolt_HvOn17 "系统所有高压在线的电柜的最小电芯电压所处CSC编号";
CM_ SG_ 2332749473 M2P_CellPst_SysMinVolt_HvOn17 "系统所有高压在线的电柜的最小电芯电压所处Cell编号";
CM_ SG_ 2332749473 M2P_SbmuPst_SysMaxTemp_LvOn17 "系统所有低压在线的电柜的最大电芯温度所处SBMU编号";
CM_ SG_ 2332749473 M2P_CscPst_SysMaxTemp_LvOn17 "系统所有低压在线的电柜的最大电芯温度所处CSC编号";
CM_ SG_ 2332749474 M2P_SbmuPst_SysMaxVolt_HvOn18 "系统所有高压在线的电柜的最大电芯电压所处SBMU编号";
CM_ SG_ 2332749474 M2P_CscPst_SysMaxVolt_HvOn18 "系统所有高压在线的电柜的最大电芯电压所处CSC编号";
CM_ SG_ 2332749474 M2P_CellPst_SysMaxVolt_HvOn18 "系统所有高压在线的电柜的最大电芯电压所处Cell编号";
CM_ SG_ 2332749474 M2P_SbmuPst_SysMinVolt_HvOn18 "系统所有高压在线的电柜的最小电芯电压所处SBMU编号";
CM_ SG_ 2332749474 M2P_CscPst_SysMinVolt_HvOn18 "系统所有高压在线的电柜的最小电芯电压所处CSC编号";
CM_ SG_ 2332749474 M2P_CellPst_SysMinVolt_HvOn18 "系统所有高压在线的电柜的最小电芯电压所处Cell编号";
CM_ SG_ 2332749474 M2P_SbmuPst_SysMaxTemp_LvOn18 "系统所有低压在线的电柜的最大电芯温度所处SBMU编号";
CM_ SG_ 2332749474 M2P_CscPst_SysMaxTemp_LvOn18 "系统所有低压在线的电柜的最大电芯温度所处CSC编号";
CM_ SG_ 2332749475 M2P_SbmuPst_SysMaxVolt_HvOn19 "系统所有高压在线的电柜的最大电芯电压所处SBMU编号";
CM_ SG_ 2332749475 M2P_CscPst_SysMaxVolt_HvOn19 "系统所有高压在线的电柜的最大电芯电压所处CSC编号";
CM_ SG_ 2332749475 M2P_CellPst_SysMaxVolt_HvOn19 "系统所有高压在线的电柜的最大电芯电压所处Cell编号";
CM_ SG_ 2332749475 M2P_SbmuPst_SysMinVolt_HvOn19 "系统所有高压在线的电柜的最小电芯电压所处SBMU编号";
CM_ SG_ 2332749475 M2P_CscPst_SysMinVolt_HvOn19 "系统所有高压在线的电柜的最小电芯电压所处CSC编号";
CM_ SG_ 2332749475 M2P_CellPst_SysMinVolt_HvOn19 "系统所有高压在线的电柜的最小电芯电压所处Cell编号";
CM_ SG_ 2332749475 M2P_SbmuPst_SysMaxTemp_LvOn19 "系统所有低压在线的电柜的最大电芯温度所处SBMU编号";
CM_ SG_ 2332749475 M2P_CscPst_SysMaxTemp_LvOn19 "系统所有低压在线的电柜的最大电芯温度所处CSC编号";
CM_ SG_ 2332749476 M2P_SbmuPst_SysMaxVolt_HvOn20 "系统所有高压在线的电柜的最大电芯电压所处SBMU编号";
CM_ SG_ 2332749476 M2P_CscPst_SysMaxVolt_HvOn20 "系统所有高压在线的电柜的最大电芯电压所处CSC编号";
CM_ SG_ 2332749476 M2P_CellPst_SysMaxVolt_HvOn20 "系统所有高压在线的电柜的最大电芯电压所处Cell编号";
CM_ SG_ 2332749476 M2P_SbmuPst_SysMinVolt_HvOn20 "系统所有高压在线的电柜的最小电芯电压所处SBMU编号";
CM_ SG_ 2332749476 M2P_CscPst_SysMinVolt_HvOn20 "系统所有高压在线的电柜的最小电芯电压所处CSC编号";
CM_ SG_ 2332749476 M2P_CellPst_SysMinVolt_HvOn20 "系统所有高压在线的电柜的最小电芯电压所处Cell编号";
CM_ SG_ 2332749476 M2P_SbmuPst_SysMaxTemp_LvOn20 "系统所有低压在线的电柜的最大电芯温度所处SBMU编号";
CM_ SG_ 2332749476 M2P_CscPst_SysMaxTemp_LvOn20 "系统所有低压在线的电柜的最大电芯温度所处CSC编号";
CM_ SG_ 2332749477 M2P_SbmuPst_SysMaxVolt_HvOn21 "系统所有高压在线的电柜的最大电芯电压所处SBMU编号";
CM_ SG_ 2332749477 M2P_CscPst_SysMaxVolt_HvOn21 "系统所有高压在线的电柜的最大电芯电压所处CSC编号";
CM_ SG_ 2332749477 M2P_CellPst_SysMaxVolt_HvOn21 "系统所有高压在线的电柜的最大电芯电压所处Cell编号";
CM_ SG_ 2332749477 M2P_SbmuPst_SysMinVolt_HvOn21 "系统所有高压在线的电柜的最小电芯电压所处SBMU编号";
CM_ SG_ 2332749477 M2P_CscPst_SysMinVolt_HvOn21 "系统所有高压在线的电柜的最小电芯电压所处CSC编号";
CM_ SG_ 2332749477 M2P_CellPst_SysMinVolt_HvOn21 "系统所有高压在线的电柜的最小电芯电压所处Cell编号";
CM_ SG_ 2332749477 M2P_SbmuPst_SysMaxTemp_LvOn21 "系统所有低压在线的电柜的最大电芯温度所处SBMU编号";
CM_ SG_ 2332749477 M2P_CscPst_SysMaxTemp_LvOn21 "系统所有低压在线的电柜的最大电芯温度所处CSC编号";
CM_ SG_ 2332749478 M2P_SbmuPst_SysMaxVolt_HvOn22 "系统所有高压在线的电柜的最大电芯电压所处SBMU编号";
CM_ SG_ 2332749478 M2P_CscPst_SysMaxVolt_HvOn22 "系统所有高压在线的电柜的最大电芯电压所处CSC编号";
CM_ SG_ 2332749478 M2P_CellPst_SysMaxVolt_HvOn22 "系统所有高压在线的电柜的最大电芯电压所处Cell编号";
CM_ SG_ 2332749478 M2P_SbmuPst_SysMinVolt_HvOn22 "系统所有高压在线的电柜的最小电芯电压所处SBMU编号";
CM_ SG_ 2332749478 M2P_CscPst_SysMinVolt_HvOn22 "系统所有高压在线的电柜的最小电芯电压所处CSC编号";
CM_ SG_ 2332749478 M2P_CellPst_SysMinVolt_HvOn22 "系统所有高压在线的电柜的最小电芯电压所处Cell编号";
CM_ SG_ 2332749478 M2P_SbmuPst_SysMaxTemp_LvOn22 "系统所有低压在线的电柜的最大电芯温度所处SBMU编号";
CM_ SG_ 2332749478 M2P_CscPst_SysMaxTemp_LvOn22 "系统所有低压在线的电柜的最大电芯温度所处CSC编号";
CM_ SG_ 2332749479 M2P_SbmuPst_SysMaxVolt_HvOn23 "系统所有高压在线的电柜的最大电芯电压所处SBMU编号";
CM_ SG_ 2332749479 M2P_CscPst_SysMaxVolt_HvOn23 "系统所有高压在线的电柜的最大电芯电压所处CSC编号";
CM_ SG_ 2332749479 M2P_CellPst_SysMaxVolt_HvOn23 "系统所有高压在线的电柜的最大电芯电压所处Cell编号";
CM_ SG_ 2332749479 M2P_SbmuPst_SysMinVolt_HvOn23 "系统所有高压在线的电柜的最小电芯电压所处SBMU编号";
CM_ SG_ 2332749479 M2P_CscPst_SysMinVolt_HvOn23 "系统所有高压在线的电柜的最小电芯电压所处CSC编号";
CM_ SG_ 2332749479 M2P_CellPst_SysMinVolt_HvOn23 "系统所有高压在线的电柜的最小电芯电压所处Cell编号";
CM_ SG_ 2332749479 M2P_SbmuPst_SysMaxTemp_LvOn23 "系统所有低压在线的电柜的最大电芯温度所处SBMU编号";
CM_ SG_ 2332749479 M2P_CscPst_SysMaxTemp_LvOn23 "系统所有低压在线的电柜的最大电芯温度所处CSC编号";
CM_ SG_ 2332749480 M2P_SbmuPst_SysMaxVolt_HvOn24 "系统所有高压在线的电柜的最大电芯电压所处SBMU编号";
CM_ SG_ 2332749480 M2P_CscPst_SysMaxVolt_HvOn24 "系统所有高压在线的电柜的最大电芯电压所处CSC编号";
CM_ SG_ 2332749480 M2P_CellPst_SysMaxVolt_HvOn24 "系统所有高压在线的电柜的最大电芯电压所处Cell编号";
CM_ SG_ 2332749480 M2P_SbmuPst_SysMinVolt_HvOn24 "系统所有高压在线的电柜的最小电芯电压所处SBMU编号";
CM_ SG_ 2332749480 M2P_CscPst_SysMinVolt_HvOn24 "系统所有高压在线的电柜的最小电芯电压所处CSC编号";
CM_ SG_ 2332749480 M2P_CellPst_SysMinVolt_HvOn24 "系统所有高压在线的电柜的最小电芯电压所处Cell编号";
CM_ SG_ 2332749480 M2P_SbmuPst_SysMaxTemp_LvOn24 "系统所有低压在线的电柜的最大电芯温度所处SBMU编号";
CM_ SG_ 2332749480 M2P_CscPst_SysMaxTemp_LvOn24 "系统所有低压在线的电柜的最大电芯温度所处CSC编号";
CM_ SG_ 2332749481 M2P_SbmuPst_SysMaxVolt_HvOn25 "系统所有高压在线的电柜的最大电芯电压所处SBMU编号";
CM_ SG_ 2332749481 M2P_CscPst_SysMaxVolt_HvOn25 "系统所有高压在线的电柜的最大电芯电压所处CSC编号";
CM_ SG_ 2332749481 M2P_CellPst_SysMaxVolt_HvOn25 "系统所有高压在线的电柜的最大电芯电压所处Cell编号";
CM_ SG_ 2332749481 M2P_SbmuPst_SysMinVolt_HvOn25 "系统所有高压在线的电柜的最小电芯电压所处SBMU编号";
CM_ SG_ 2332749481 M2P_CscPst_SysMinVolt_HvOn25 "系统所有高压在线的电柜的最小电芯电压所处CSC编号";
CM_ SG_ 2332749481 M2P_CellPst_SysMinVolt_HvOn25 "系统所有高压在线的电柜的最小电芯电压所处Cell编号";
CM_ SG_ 2332749481 M2P_SbmuPst_SysMaxTemp_LvOn25 "系统所有低压在线的电柜的最大电芯温度所处SBMU编号";
CM_ SG_ 2332749481 M2P_CscPst_SysMaxTemp_LvOn25 "系统所有低压在线的电柜的最大电芯温度所处CSC编号";
CM_ SG_ 2332749482 M2P_SbmuPst_SysMaxVolt_HvOn26 "系统所有高压在线的电柜的最大电芯电压所处SBMU编号";
CM_ SG_ 2332749482 M2P_CscPst_SysMaxVolt_HvOn26 "系统所有高压在线的电柜的最大电芯电压所处CSC编号";
CM_ SG_ 2332749482 M2P_CellPst_SysMaxVolt_HvOn26 "系统所有高压在线的电柜的最大电芯电压所处Cell编号";
CM_ SG_ 2332749482 M2P_SbmuPst_SysMinVolt_HvOn26 "系统所有高压在线的电柜的最小电芯电压所处SBMU编号";
CM_ SG_ 2332749482 M2P_CscPst_SysMinVolt_HvOn26 "系统所有高压在线的电柜的最小电芯电压所处CSC编号";
CM_ SG_ 2332749482 M2P_CellPst_SysMinVolt_HvOn26 "系统所有高压在线的电柜的最小电芯电压所处Cell编号";
CM_ SG_ 2332749482 M2P_SbmuPst_SysMaxTemp_LvOn26 "系统所有低压在线的电柜的最大电芯温度所处SBMU编号";
CM_ SG_ 2332749482 M2P_CscPst_SysMaxTemp_LvOn26 "系统所有低压在线的电柜的最大电芯温度所处CSC编号";
CM_ SG_ 2332749483 M2P_SbmuPst_SysMaxVolt_HvOn27 "系统所有高压在线的电柜的最大电芯电压所处SBMU编号";
CM_ SG_ 2332749483 M2P_CscPst_SysMaxVolt_HvOn27 "系统所有高压在线的电柜的最大电芯电压所处CSC编号";
CM_ SG_ 2332749483 M2P_CellPst_SysMaxVolt_HvOn27 "系统所有高压在线的电柜的最大电芯电压所处Cell编号";
CM_ SG_ 2332749483 M2P_SbmuPst_SysMinVolt_HvOn27 "系统所有高压在线的电柜的最小电芯电压所处SBMU编号";
CM_ SG_ 2332749483 M2P_CscPst_SysMinVolt_HvOn27 "系统所有高压在线的电柜的最小电芯电压所处CSC编号";
CM_ SG_ 2332749483 M2P_CellPst_SysMinVolt_HvOn27 "系统所有高压在线的电柜的最小电芯电压所处Cell编号";
CM_ SG_ 2332749483 M2P_SbmuPst_SysMaxTemp_LvOn27 "系统所有低压在线的电柜的最大电芯温度所处SBMU编号";
CM_ SG_ 2332749483 M2P_CscPst_SysMaxTemp_LvOn27 "系统所有低压在线的电柜的最大电芯温度所处CSC编号";
CM_ SG_ 2332749484 M2P_SbmuPst_SysMaxVolt_HvOn28 "系统所有高压在线的电柜的最大电芯电压所处SBMU编号";
CM_ SG_ 2332749484 M2P_CscPst_SysMaxVolt_HvOn28 "系统所有高压在线的电柜的最大电芯电压所处CSC编号";
CM_ SG_ 2332749484 M2P_CellPst_SysMaxVolt_HvOn28 "系统所有高压在线的电柜的最大电芯电压所处Cell编号";
CM_ SG_ 2332749484 M2P_SbmuPst_SysMinVolt_HvOn28 "系统所有高压在线的电柜的最小电芯电压所处SBMU编号";
CM_ SG_ 2332749484 M2P_CscPst_SysMinVolt_HvOn28 "系统所有高压在线的电柜的最小电芯电压所处CSC编号";
CM_ SG_ 2332749484 M2P_CellPst_SysMinVolt_HvOn28 "系统所有高压在线的电柜的最小电芯电压所处Cell编号";
CM_ SG_ 2332749484 M2P_SbmuPst_SysMaxTemp_LvOn28 "系统所有低压在线的电柜的最大电芯温度所处SBMU编号";
CM_ SG_ 2332749484 M2P_CscPst_SysMaxTemp_LvOn28 "系统所有低压在线的电柜的最大电芯温度所处CSC编号";
CM_ SG_ 2332749485 M2P_SbmuPst_SysMaxVolt_HvOn29 "系统所有高压在线的电柜的最大电芯电压所处SBMU编号";
CM_ SG_ 2332749485 M2P_CscPst_SysMaxVolt_HvOn29 "系统所有高压在线的电柜的最大电芯电压所处CSC编号";
CM_ SG_ 2332749485 M2P_CellPst_SysMaxVolt_HvOn29 "系统所有高压在线的电柜的最大电芯电压所处Cell编号";
CM_ SG_ 2332749485 M2P_SbmuPst_SysMinVolt_HvOn29 "系统所有高压在线的电柜的最小电芯电压所处SBMU编号";
CM_ SG_ 2332749485 M2P_CscPst_SysMinVolt_HvOn29 "系统所有高压在线的电柜的最小电芯电压所处CSC编号";
CM_ SG_ 2332749485 M2P_CellPst_SysMinVolt_HvOn29 "系统所有高压在线的电柜的最小电芯电压所处Cell编号";
CM_ SG_ 2332749485 M2P_SbmuPst_SysMaxTemp_LvOn29 "系统所有低压在线的电柜的最大电芯温度所处SBMU编号";
CM_ SG_ 2332749485 M2P_CscPst_SysMaxTemp_LvOn29 "系统所有低压在线的电柜的最大电芯温度所处CSC编号";
CM_ SG_ 2332749486 M2P_SbmuPst_SysMaxVolt_HvOn30 "系统所有高压在线的电柜的最大电芯电压所处SBMU编号";
CM_ SG_ 2332749486 M2P_CscPst_SysMaxVolt_HvOn30 "系统所有高压在线的电柜的最大电芯电压所处CSC编号";
CM_ SG_ 2332749486 M2P_CellPst_SysMaxVolt_HvOn30 "系统所有高压在线的电柜的最大电芯电压所处Cell编号";
CM_ SG_ 2332749486 M2P_SbmuPst_SysMinVolt_HvOn30 "系统所有高压在线的电柜的最小电芯电压所处SBMU编号";
CM_ SG_ 2332749486 M2P_CscPst_SysMinVolt_HvOn30 "系统所有高压在线的电柜的最小电芯电压所处CSC编号";
CM_ SG_ 2332749486 M2P_CellPst_SysMinVolt_HvOn30 "系统所有高压在线的电柜的最小电芯电压所处Cell编号";
CM_ SG_ 2332749486 M2P_SbmuPst_SysMaxTemp_LvOn30 "系统所有低压在线的电柜的最大电芯温度所处SBMU编号";
CM_ SG_ 2332749486 M2P_CscPst_SysMaxTemp_LvOn30 "系统所有低压在线的电柜的最大电芯温度所处CSC编号";
CM_ SG_ 2332749487 M2P_SbmuPst_SysMaxVolt_HvOn31 "系统所有高压在线的电柜的最大电芯电压所处SBMU编号";
CM_ SG_ 2332749487 M2P_CscPst_SysMaxVolt_HvOn31 "系统所有高压在线的电柜的最大电芯电压所处CSC编号";
CM_ SG_ 2332749487 M2P_CellPst_SysMaxVolt_HvOn31 "系统所有高压在线的电柜的最大电芯电压所处Cell编号";
CM_ SG_ 2332749487 M2P_SbmuPst_SysMinVolt_HvOn31 "系统所有高压在线的电柜的最小电芯电压所处SBMU编号";
CM_ SG_ 2332749487 M2P_CscPst_SysMinVolt_HvOn31 "系统所有高压在线的电柜的最小电芯电压所处CSC编号";
CM_ SG_ 2332749487 M2P_CellPst_SysMinVolt_HvOn31 "系统所有高压在线的电柜的最小电芯电压所处Cell编号";
CM_ SG_ 2332749487 M2P_SbmuPst_SysMaxTemp_LvOn31 "系统所有低压在线的电柜的最大电芯温度所处SBMU编号";
CM_ SG_ 2332749487 M2P_CscPst_SysMaxTemp_LvOn31 "系统所有低压在线的电柜的最大电芯温度所处CSC编号";
CM_ SG_ 2332814993 M2P_SbmuPst_SysMaxVolt_LvOn01 "系统所有低压在线的电柜的最大电芯电压所处SBMU编号";
CM_ SG_ 2332814993 M2P_CscPst_SysMaxVolt_LvOn01 "系统所有低压在线的电柜的最大电芯电压所处CSC编号";
CM_ SG_ 2332814993 M2P_CellPst_SysMaxVolt_LvOn01 "系统所有低压在线的电柜的最大电芯电压所处Cell编号";
CM_ SG_ 2332814993 M2P_SbmuPst_SysMinVolt_LvOn01 "系统所有低压在线的电柜的最小电芯电压所处SBMU编号";
CM_ SG_ 2332814993 M2P_CscPst_SysMinVolt_LvOn01 "系统所有低压在线的电柜的最小电芯电压所处CSC编号";
CM_ SG_ 2332814993 M2P_CellPst_SysMinVolt_LvOn01 "系统所有低压在线的电柜的最小电芯电压所处Cell编号";
CM_ SG_ 2332814993 M2P_SbmuPst_SysMinTemp_LvOn01 "系统所有低压在线的电柜的最小电芯温度所处SBMU编号";
CM_ SG_ 2332814993 M2P_CscPst_SysMinTemp_LvOn01 "系统所有低压在线的电柜的最小电芯温度所处CSC编号";
CM_ SG_ 2332814994 M2P_SbmuPst_SysMaxVolt_LvOn02 "系统所有低压在线的电柜的最大电芯电压所处SBMU编号";
CM_ SG_ 2332814994 M2P_CscPst_SysMaxVolt_LvOn02 "系统所有低压在线的电柜的最大电芯电压所处CSC编号";
CM_ SG_ 2332814994 M2P_CellPst_SysMaxVolt_LvOn02 "系统所有低压在线的电柜的最大电芯电压所处Cell编号";
CM_ SG_ 2332814994 M2P_SbmuPst_SysMinVolt_LvOn02 "系统所有低压在线的电柜的最小电芯电压所处SBMU编号";
CM_ SG_ 2332814994 M2P_CscPst_SysMinVolt_LvOn02 "系统所有低压在线的电柜的最小电芯电压所处CSC编号";
CM_ SG_ 2332814994 M2P_CellPst_SysMinVolt_LvOn02 "系统所有低压在线的电柜的最小电芯电压所处Cell编号";
CM_ SG_ 2332814994 M2P_SbmuPst_SysMinTemp_LvOn02 "系统所有低压在线的电柜的最小电芯温度所处SBMU编号";
CM_ SG_ 2332814994 M2P_CscPst_SysMinTemp_LvOn02 "系统所有低压在线的电柜的最小电芯温度所处CSC编号";
CM_ SG_ 2332814995 M2P_SbmuPst_SysMaxVolt_LvOn03 "系统所有低压在线的电柜的最大电芯电压所处SBMU编号";
CM_ SG_ 2332814995 M2P_CscPst_SysMaxVolt_LvOn03 "系统所有低压在线的电柜的最大电芯电压所处CSC编号";
CM_ SG_ 2332814995 M2P_CellPst_SysMaxVolt_LvOn03 "系统所有低压在线的电柜的最大电芯电压所处Cell编号";
CM_ SG_ 2332814995 M2P_SbmuPst_SysMinVolt_LvOn03 "系统所有低压在线的电柜的最小电芯电压所处SBMU编号";
CM_ SG_ 2332814995 M2P_CscPst_SysMinVolt_LvOn03 "系统所有低压在线的电柜的最小电芯电压所处CSC编号";
CM_ SG_ 2332814995 M2P_CellPst_SysMinVolt_LvOn03 "系统所有低压在线的电柜的最小电芯电压所处Cell编号";
CM_ SG_ 2332814995 M2P_SbmuPst_SysMinTemp_LvOn03 "系统所有低压在线的电柜的最小电芯温度所处SBMU编号";
CM_ SG_ 2332814995 M2P_CscPst_SysMinTemp_LvOn03 "系统所有低压在线的电柜的最小电芯温度所处CSC编号";
CM_ SG_ 2332814996 M2P_SbmuPst_SysMaxVolt_LvOn04 "系统所有低压在线的电柜的最大电芯电压所处SBMU编号";
CM_ SG_ 2332814996 M2P_CscPst_SysMaxVolt_LvOn04 "系统所有低压在线的电柜的最大电芯电压所处CSC编号";
CM_ SG_ 2332814996 M2P_CellPst_SysMaxVolt_LvOn04 "系统所有低压在线的电柜的最大电芯电压所处Cell编号";
CM_ SG_ 2332814996 M2P_SbmuPst_SysMinVolt_LvOn04 "系统所有低压在线的电柜的最小电芯电压所处SBMU编号";
CM_ SG_ 2332814996 M2P_CscPst_SysMinVolt_LvOn04 "系统所有低压在线的电柜的最小电芯电压所处CSC编号";
CM_ SG_ 2332814996 M2P_CellPst_SysMinVolt_LvOn04 "系统所有低压在线的电柜的最小电芯电压所处Cell编号";
CM_ SG_ 2332814996 M2P_SbmuPst_SysMinTemp_LvOn04 "系统所有低压在线的电柜的最小电芯温度所处SBMU编号";
CM_ SG_ 2332814996 M2P_CscPst_SysMinTemp_LvOn04 "系统所有低压在线的电柜的最小电芯温度所处CSC编号";
CM_ SG_ 2332814997 M2P_SbmuPst_SysMaxVolt_LvOn05 "系统所有低压在线的电柜的最大电芯电压所处SBMU编号";
CM_ SG_ 2332814997 M2P_CscPst_SysMaxVolt_LvOn05 "系统所有低压在线的电柜的最大电芯电压所处CSC编号";
CM_ SG_ 2332814997 M2P_CellPst_SysMaxVolt_LvOn05 "系统所有低压在线的电柜的最大电芯电压所处Cell编号";
CM_ SG_ 2332814997 M2P_SbmuPst_SysMinVolt_LvOn05 "系统所有低压在线的电柜的最小电芯电压所处SBMU编号";
CM_ SG_ 2332814997 M2P_CscPst_SysMinVolt_LvOn05 "系统所有低压在线的电柜的最小电芯电压所处CSC编号";
CM_ SG_ 2332814997 M2P_CellPst_SysMinVolt_LvOn05 "系统所有低压在线的电柜的最小电芯电压所处Cell编号";
CM_ SG_ 2332814997 M2P_SbmuPst_SysMinTemp_LvOn05 "系统所有低压在线的电柜的最小电芯温度所处SBMU编号";
CM_ SG_ 2332814997 M2P_CscPst_SysMinTemp_LvOn05 "系统所有低压在线的电柜的最小电芯温度所处CSC编号";
CM_ SG_ 2332814998 M2P_SbmuPst_SysMaxVolt_LvOn06 "系统所有低压在线的电柜的最大电芯电压所处SBMU编号";
CM_ SG_ 2332814998 M2P_CscPst_SysMaxVolt_LvOn06 "系统所有低压在线的电柜的最大电芯电压所处CSC编号";
CM_ SG_ 2332814998 M2P_CellPst_SysMaxVolt_LvOn06 "系统所有低压在线的电柜的最大电芯电压所处Cell编号";
CM_ SG_ 2332814998 M2P_SbmuPst_SysMinVolt_LvOn06 "系统所有低压在线的电柜的最小电芯电压所处SBMU编号";
CM_ SG_ 2332814998 M2P_CscPst_SysMinVolt_LvOn06 "系统所有低压在线的电柜的最小电芯电压所处CSC编号";
CM_ SG_ 2332814998 M2P_CellPst_SysMinVolt_LvOn06 "系统所有低压在线的电柜的最小电芯电压所处Cell编号";
CM_ SG_ 2332814998 M2P_SbmuPst_SysMinTemp_LvOn06 "系统所有低压在线的电柜的最小电芯温度所处SBMU编号";
CM_ SG_ 2332814998 M2P_CscPst_SysMinTemp_LvOn06 "系统所有低压在线的电柜的最小电芯温度所处CSC编号";
CM_ SG_ 2332814999 M2P_SbmuPst_SysMaxVolt_LvOn07 "系统所有低压在线的电柜的最大电芯电压所处SBMU编号";
CM_ SG_ 2332814999 M2P_CscPst_SysMaxVolt_LvOn07 "系统所有低压在线的电柜的最大电芯电压所处CSC编号";
CM_ SG_ 2332814999 M2P_CellPst_SysMaxVolt_LvOn07 "系统所有低压在线的电柜的最大电芯电压所处Cell编号";
CM_ SG_ 2332814999 M2P_SbmuPst_SysMinVolt_LvOn07 "系统所有低压在线的电柜的最小电芯电压所处SBMU编号";
CM_ SG_ 2332814999 M2P_CscPst_SysMinVolt_LvOn07 "系统所有低压在线的电柜的最小电芯电压所处CSC编号";
CM_ SG_ 2332814999 M2P_CellPst_SysMinVolt_LvOn07 "系统所有低压在线的电柜的最小电芯电压所处Cell编号";
CM_ SG_ 2332814999 M2P_SbmuPst_SysMinTemp_LvOn07 "系统所有低压在线的电柜的最小电芯温度所处SBMU编号";
CM_ SG_ 2332814999 M2P_CscPst_SysMinTemp_LvOn07 "系统所有低压在线的电柜的最小电芯温度所处CSC编号";
CM_ SG_ 2332815000 M2P_SbmuPst_SysMaxVolt_LvOn08 "系统所有低压在线的电柜的最大电芯电压所处SBMU编号";
CM_ SG_ 2332815000 M2P_CscPst_SysMaxVolt_LvOn08 "系统所有低压在线的电柜的最大电芯电压所处CSC编号";
CM_ SG_ 2332815000 M2P_CellPst_SysMaxVolt_LvOn08 "系统所有低压在线的电柜的最大电芯电压所处Cell编号";
CM_ SG_ 2332815000 M2P_SbmuPst_SysMinVolt_LvOn08 "系统所有低压在线的电柜的最小电芯电压所处SBMU编号";
CM_ SG_ 2332815000 M2P_CscPst_SysMinVolt_LvOn08 "系统所有低压在线的电柜的最小电芯电压所处CSC编号";
CM_ SG_ 2332815000 M2P_CellPst_SysMinVolt_LvOn08 "系统所有低压在线的电柜的最小电芯电压所处Cell编号";
CM_ SG_ 2332815000 M2P_SbmuPst_SysMinTemp_LvOn08 "系统所有低压在线的电柜的最小电芯温度所处SBMU编号";
CM_ SG_ 2332815000 M2P_CscPst_SysMinTemp_LvOn08 "系统所有低压在线的电柜的最小电芯温度所处CSC编号";
CM_ SG_ 2332815001 M2P_SbmuPst_SysMaxVolt_LvOn09 "系统所有低压在线的电柜的最大电芯电压所处SBMU编号";
CM_ SG_ 2332815001 M2P_CscPst_SysMaxVolt_LvOn09 "系统所有低压在线的电柜的最大电芯电压所处CSC编号";
CM_ SG_ 2332815001 M2P_CellPst_SysMaxVolt_LvOn09 "系统所有低压在线的电柜的最大电芯电压所处Cell编号";
CM_ SG_ 2332815001 M2P_SbmuPst_SysMinVolt_LvOn09 "系统所有低压在线的电柜的最小电芯电压所处SBMU编号";
CM_ SG_ 2332815001 M2P_CscPst_SysMinVolt_LvOn09 "系统所有低压在线的电柜的最小电芯电压所处CSC编号";
CM_ SG_ 2332815001 M2P_CellPst_SysMinVolt_LvOn09 "系统所有低压在线的电柜的最小电芯电压所处Cell编号";
CM_ SG_ 2332815001 M2P_SbmuPst_SysMinTemp_LvOn09 "系统所有低压在线的电柜的最小电芯温度所处SBMU编号";
CM_ SG_ 2332815001 M2P_CscPst_SysMinTemp_LvOn09 "系统所有低压在线的电柜的最小电芯温度所处CSC编号";
CM_ SG_ 2332815002 M2P_SbmuPst_SysMaxVolt_LvOn10 "系统所有低压在线的电柜的最大电芯电压所处SBMU编号";
CM_ SG_ 2332815002 M2P_CscPst_SysMaxVolt_LvOn10 "系统所有低压在线的电柜的最大电芯电压所处CSC编号";
CM_ SG_ 2332815002 M2P_CellPst_SysMaxVolt_LvOn10 "系统所有低压在线的电柜的最大电芯电压所处Cell编号";
CM_ SG_ 2332815002 M2P_SbmuPst_SysMinVolt_LvOn10 "系统所有低压在线的电柜的最小电芯电压所处SBMU编号";
CM_ SG_ 2332815002 M2P_CscPst_SysMinVolt_LvOn10 "系统所有低压在线的电柜的最小电芯电压所处CSC编号";
CM_ SG_ 2332815002 M2P_CellPst_SysMinVolt_LvOn10 "系统所有低压在线的电柜的最小电芯电压所处Cell编号";
CM_ SG_ 2332815002 M2P_SbmuPst_SysMinTemp_LvOn10 "系统所有低压在线的电柜的最小电芯温度所处SBMU编号";
CM_ SG_ 2332815002 M2P_CscPst_SysMinTemp_LvOn10 "系统所有低压在线的电柜的最小电芯温度所处CSC编号";
CM_ SG_ 2332815003 M2P_SbmuPst_SysMaxVolt_LvOn11 "系统所有低压在线的电柜的最大电芯电压所处SBMU编号";
CM_ SG_ 2332815003 M2P_CscPst_SysMaxVolt_LvOn11 "系统所有低压在线的电柜的最大电芯电压所处CSC编号";
CM_ SG_ 2332815003 M2P_CellPst_SysMaxVolt_LvOn11 "系统所有低压在线的电柜的最大电芯电压所处Cell编号";
CM_ SG_ 2332815003 M2P_SbmuPst_SysMinVolt_LvOn11 "系统所有低压在线的电柜的最小电芯电压所处SBMU编号";
CM_ SG_ 2332815003 M2P_CscPst_SysMinVolt_LvOn11 "系统所有低压在线的电柜的最小电芯电压所处CSC编号";
CM_ SG_ 2332815003 M2P_CellPst_SysMinVolt_LvOn11 "系统所有低压在线的电柜的最小电芯电压所处Cell编号";
CM_ SG_ 2332815003 M2P_SbmuPst_SysMinTemp_LvOn11 "系统所有低压在线的电柜的最小电芯温度所处SBMU编号";
CM_ SG_ 2332815003 M2P_CscPst_SysMinTemp_LvOn11 "系统所有低压在线的电柜的最小电芯温度所处CSC编号";
CM_ SG_ 2332815004 M2P_SbmuPst_SysMaxVolt_LvOn12 "系统所有低压在线的电柜的最大电芯电压所处SBMU编号";
CM_ SG_ 2332815004 M2P_CscPst_SysMaxVolt_LvOn12 "系统所有低压在线的电柜的最大电芯电压所处CSC编号";
CM_ SG_ 2332815004 M2P_CellPst_SysMaxVolt_LvOn12 "系统所有低压在线的电柜的最大电芯电压所处Cell编号";
CM_ SG_ 2332815004 M2P_SbmuPst_SysMinVolt_LvOn12 "系统所有低压在线的电柜的最小电芯电压所处SBMU编号";
CM_ SG_ 2332815004 M2P_CscPst_SysMinVolt_LvOn12 "系统所有低压在线的电柜的最小电芯电压所处CSC编号";
CM_ SG_ 2332815004 M2P_CellPst_SysMinVolt_LvOn12 "系统所有低压在线的电柜的最小电芯电压所处Cell编号";
CM_ SG_ 2332815004 M2P_SbmuPst_SysMinTemp_LvOn12 "系统所有低压在线的电柜的最小电芯温度所处SBMU编号";
CM_ SG_ 2332815004 M2P_CscPst_SysMinTemp_LvOn12 "系统所有低压在线的电柜的最小电芯温度所处CSC编号";
CM_ SG_ 2332815005 M2P_SbmuPst_SysMaxVolt_LvOn13 "系统所有低压在线的电柜的最大电芯电压所处SBMU编号";
CM_ SG_ 2332815005 M2P_CscPst_SysMaxVolt_LvOn13 "系统所有低压在线的电柜的最大电芯电压所处CSC编号";
CM_ SG_ 2332815005 M2P_CellPst_SysMaxVolt_LvOn13 "系统所有低压在线的电柜的最大电芯电压所处Cell编号";
CM_ SG_ 2332815005 M2P_SbmuPst_SysMinVolt_LvOn13 "系统所有低压在线的电柜的最小电芯电压所处SBMU编号";
CM_ SG_ 2332815005 M2P_CscPst_SysMinVolt_LvOn13 "系统所有低压在线的电柜的最小电芯电压所处CSC编号";
CM_ SG_ 2332815005 M2P_CellPst_SysMinVolt_LvOn13 "系统所有低压在线的电柜的最小电芯电压所处Cell编号";
CM_ SG_ 2332815005 M2P_SbmuPst_SysMinTemp_LvOn13 "系统所有低压在线的电柜的最小电芯温度所处SBMU编号";
CM_ SG_ 2332815005 M2P_CscPst_SysMinTemp_LvOn13 "系统所有低压在线的电柜的最小电芯温度所处CSC编号";
CM_ SG_ 2332815006 M2P_SbmuPst_SysMaxVolt_LvOn14 "系统所有低压在线的电柜的最大电芯电压所处SBMU编号";
CM_ SG_ 2332815006 M2P_CscPst_SysMaxVolt_LvOn14 "系统所有低压在线的电柜的最大电芯电压所处CSC编号";
CM_ SG_ 2332815006 M2P_CellPst_SysMaxVolt_LvOn14 "系统所有低压在线的电柜的最大电芯电压所处Cell编号";
CM_ SG_ 2332815006 M2P_SbmuPst_SysMinVolt_LvOn14 "系统所有低压在线的电柜的最小电芯电压所处SBMU编号";
CM_ SG_ 2332815006 M2P_CscPst_SysMinVolt_LvOn14 "系统所有低压在线的电柜的最小电芯电压所处CSC编号";
CM_ SG_ 2332815006 M2P_CellPst_SysMinVolt_LvOn14 "系统所有低压在线的电柜的最小电芯电压所处Cell编号";
CM_ SG_ 2332815006 M2P_SbmuPst_SysMinTemp_LvOn14 "系统所有低压在线的电柜的最小电芯温度所处SBMU编号";
CM_ SG_ 2332815006 M2P_CscPst_SysMinTemp_LvOn14 "系统所有低压在线的电柜的最小电芯温度所处CSC编号";
CM_ SG_ 2332815007 M2P_SbmuPst_SysMaxVolt_LvOn15 "系统所有低压在线的电柜的最大电芯电压所处SBMU编号";
CM_ SG_ 2332815007 M2P_CscPst_SysMaxVolt_LvOn15 "系统所有低压在线的电柜的最大电芯电压所处CSC编号";
CM_ SG_ 2332815007 M2P_CellPst_SysMaxVolt_LvOn15 "系统所有低压在线的电柜的最大电芯电压所处Cell编号";
CM_ SG_ 2332815007 M2P_SbmuPst_SysMinVolt_LvOn15 "系统所有低压在线的电柜的最小电芯电压所处SBMU编号";
CM_ SG_ 2332815007 M2P_CscPst_SysMinVolt_LvOn15 "系统所有低压在线的电柜的最小电芯电压所处CSC编号";
CM_ SG_ 2332815007 M2P_CellPst_SysMinVolt_LvOn15 "系统所有低压在线的电柜的最小电芯电压所处Cell编号";
CM_ SG_ 2332815007 M2P_SbmuPst_SysMinTemp_LvOn15 "系统所有低压在线的电柜的最小电芯温度所处SBMU编号";
CM_ SG_ 2332815007 M2P_CscPst_SysMinTemp_LvOn15 "系统所有低压在线的电柜的最小电芯温度所处CSC编号";
CM_ SG_ 2332815008 M2P_SbmuPst_SysMaxVolt_LvOn16 "系统所有低压在线的电柜的最大电芯电压所处SBMU编号";
CM_ SG_ 2332815008 M2P_CscPst_SysMaxVolt_LvOn16 "系统所有低压在线的电柜的最大电芯电压所处CSC编号";
CM_ SG_ 2332815008 M2P_CellPst_SysMaxVolt_LvOn16 "系统所有低压在线的电柜的最大电芯电压所处Cell编号";
CM_ SG_ 2332815008 M2P_SbmuPst_SysMinVolt_LvOn16 "系统所有低压在线的电柜的最小电芯电压所处SBMU编号";
CM_ SG_ 2332815008 M2P_CscPst_SysMinVolt_LvOn16 "系统所有低压在线的电柜的最小电芯电压所处CSC编号";
CM_ SG_ 2332815008 M2P_CellPst_SysMinVolt_LvOn16 "系统所有低压在线的电柜的最小电芯电压所处Cell编号";
CM_ SG_ 2332815008 M2P_SbmuPst_SysMinTemp_LvOn16 "系统所有低压在线的电柜的最小电芯温度所处SBMU编号";
CM_ SG_ 2332815008 M2P_CscPst_SysMinTemp_LvOn16 "系统所有低压在线的电柜的最小电芯温度所处CSC编号";
CM_ SG_ 2332815009 M2P_SbmuPst_SysMaxVolt_LvOn17 "系统所有低压在线的电柜的最大电芯电压所处SBMU编号";
CM_ SG_ 2332815009 M2P_CscPst_SysMaxVolt_LvOn17 "系统所有低压在线的电柜的最大电芯电压所处CSC编号";
CM_ SG_ 2332815009 M2P_CellPst_SysMaxVolt_LvOn17 "系统所有低压在线的电柜的最大电芯电压所处Cell编号";
CM_ SG_ 2332815009 M2P_SbmuPst_SysMinVolt_LvOn17 "系统所有低压在线的电柜的最小电芯电压所处SBMU编号";
CM_ SG_ 2332815009 M2P_CscPst_SysMinVolt_LvOn17 "系统所有低压在线的电柜的最小电芯电压所处CSC编号";
CM_ SG_ 2332815009 M2P_CellPst_SysMinVolt_LvOn17 "系统所有低压在线的电柜的最小电芯电压所处Cell编号";
CM_ SG_ 2332815009 M2P_SbmuPst_SysMinTemp_LvOn17 "系统所有低压在线的电柜的最小电芯温度所处SBMU编号";
CM_ SG_ 2332815009 M2P_CscPst_SysMinTemp_LvOn17 "系统所有低压在线的电柜的最小电芯温度所处CSC编号";
CM_ SG_ 2332815010 M2P_SbmuPst_SysMaxVolt_LvOn18 "系统所有低压在线的电柜的最大电芯电压所处SBMU编号";
CM_ SG_ 2332815010 M2P_CscPst_SysMaxVolt_LvOn18 "系统所有低压在线的电柜的最大电芯电压所处CSC编号";
CM_ SG_ 2332815010 M2P_CellPst_SysMaxVolt_LvOn18 "系统所有低压在线的电柜的最大电芯电压所处Cell编号";
CM_ SG_ 2332815010 M2P_SbmuPst_SysMinVolt_LvOn18 "系统所有低压在线的电柜的最小电芯电压所处SBMU编号";
CM_ SG_ 2332815010 M2P_CscPst_SysMinVolt_LvOn18 "系统所有低压在线的电柜的最小电芯电压所处CSC编号";
CM_ SG_ 2332815010 M2P_CellPst_SysMinVolt_LvOn18 "系统所有低压在线的电柜的最小电芯电压所处Cell编号";
CM_ SG_ 2332815010 M2P_SbmuPst_SysMinTemp_LvOn18 "系统所有低压在线的电柜的最小电芯温度所处SBMU编号";
CM_ SG_ 2332815010 M2P_CscPst_SysMinTemp_LvOn18 "系统所有低压在线的电柜的最小电芯温度所处CSC编号";
CM_ SG_ 2332815011 M2P_SbmuPst_SysMaxVolt_LvOn19 "系统所有低压在线的电柜的最大电芯电压所处SBMU编号";
CM_ SG_ 2332815011 M2P_CscPst_SysMaxVolt_LvOn19 "系统所有低压在线的电柜的最大电芯电压所处CSC编号";
CM_ SG_ 2332815011 M2P_CellPst_SysMaxVolt_LvOn19 "系统所有低压在线的电柜的最大电芯电压所处Cell编号";
CM_ SG_ 2332815011 M2P_SbmuPst_SysMinVolt_LvOn19 "系统所有低压在线的电柜的最小电芯电压所处SBMU编号";
CM_ SG_ 2332815011 M2P_CscPst_SysMinVolt_LvOn19 "系统所有低压在线的电柜的最小电芯电压所处CSC编号";
CM_ SG_ 2332815011 M2P_CellPst_SysMinVolt_LvOn19 "系统所有低压在线的电柜的最小电芯电压所处Cell编号";
CM_ SG_ 2332815011 M2P_SbmuPst_SysMinTemp_LvOn19 "系统所有低压在线的电柜的最小电芯温度所处SBMU编号";
CM_ SG_ 2332815011 M2P_CscPst_SysMinTemp_LvOn19 "系统所有低压在线的电柜的最小电芯温度所处CSC编号";
CM_ SG_ 2332815012 M2P_SbmuPst_SysMaxVolt_LvOn20 "系统所有低压在线的电柜的最大电芯电压所处SBMU编号";
CM_ SG_ 2332815012 M2P_CscPst_SysMaxVolt_LvOn20 "系统所有低压在线的电柜的最大电芯电压所处CSC编号";
CM_ SG_ 2332815012 M2P_CellPst_SysMaxVolt_LvOn20 "系统所有低压在线的电柜的最大电芯电压所处Cell编号";
CM_ SG_ 2332815012 M2P_SbmuPst_SysMinVolt_LvOn20 "系统所有低压在线的电柜的最小电芯电压所处SBMU编号";
CM_ SG_ 2332815012 M2P_CscPst_SysMinVolt_LvOn20 "系统所有低压在线的电柜的最小电芯电压所处CSC编号";
CM_ SG_ 2332815012 M2P_CellPst_SysMinVolt_LvOn20 "系统所有低压在线的电柜的最小电芯电压所处Cell编号";
CM_ SG_ 2332815012 M2P_SbmuPst_SysMinTemp_LvOn20 "系统所有低压在线的电柜的最小电芯温度所处SBMU编号";
CM_ SG_ 2332815012 M2P_CscPst_SysMinTemp_LvOn20 "系统所有低压在线的电柜的最小电芯温度所处CSC编号";
CM_ SG_ 2332815013 M2P_SbmuPst_SysMaxVolt_LvOn21 "系统所有低压在线的电柜的最大电芯电压所处SBMU编号";
CM_ SG_ 2332815013 M2P_CscPst_SysMaxVolt_LvOn21 "系统所有低压在线的电柜的最大电芯电压所处CSC编号";
CM_ SG_ 2332815013 M2P_CellPst_SysMaxVolt_LvOn21 "系统所有低压在线的电柜的最大电芯电压所处Cell编号";
CM_ SG_ 2332815013 M2P_SbmuPst_SysMinVolt_LvOn21 "系统所有低压在线的电柜的最小电芯电压所处SBMU编号";
CM_ SG_ 2332815013 M2P_CscPst_SysMinVolt_LvOn21 "系统所有低压在线的电柜的最小电芯电压所处CSC编号";
CM_ SG_ 2332815013 M2P_CellPst_SysMinVolt_LvOn21 "系统所有低压在线的电柜的最小电芯电压所处Cell编号";
CM_ SG_ 2332815013 M2P_SbmuPst_SysMinTemp_LvOn21 "系统所有低压在线的电柜的最小电芯温度所处SBMU编号";
CM_ SG_ 2332815013 M2P_CscPst_SysMinTemp_LvOn21 "系统所有低压在线的电柜的最小电芯温度所处CSC编号";
CM_ SG_ 2332815014 M2P_SbmuPst_SysMaxVolt_LvOn22 "系统所有低压在线的电柜的最大电芯电压所处SBMU编号";
CM_ SG_ 2332815014 M2P_CscPst_SysMaxVolt_LvOn22 "系统所有低压在线的电柜的最大电芯电压所处CSC编号";
CM_ SG_ 2332815014 M2P_CellPst_SysMaxVolt_LvOn22 "系统所有低压在线的电柜的最大电芯电压所处Cell编号";
CM_ SG_ 2332815014 M2P_SbmuPst_SysMinVolt_LvOn22 "系统所有低压在线的电柜的最小电芯电压所处SBMU编号";
CM_ SG_ 2332815014 M2P_CscPst_SysMinVolt_LvOn22 "系统所有低压在线的电柜的最小电芯电压所处CSC编号";
CM_ SG_ 2332815014 M2P_CellPst_SysMinVolt_LvOn22 "系统所有低压在线的电柜的最小电芯电压所处Cell编号";
CM_ SG_ 2332815014 M2P_SbmuPst_SysMinTemp_LvOn22 "系统所有低压在线的电柜的最小电芯温度所处SBMU编号";
CM_ SG_ 2332815014 M2P_CscPst_SysMinTemp_LvOn22 "系统所有低压在线的电柜的最小电芯温度所处CSC编号";
CM_ SG_ 2332815015 M2P_SbmuPst_SysMaxVolt_LvOn23 "系统所有低压在线的电柜的最大电芯电压所处SBMU编号";
CM_ SG_ 2332815015 M2P_CscPst_SysMaxVolt_LvOn23 "系统所有低压在线的电柜的最大电芯电压所处CSC编号";
CM_ SG_ 2332815015 M2P_CellPst_SysMaxVolt_LvOn23 "系统所有低压在线的电柜的最大电芯电压所处Cell编号";
CM_ SG_ 2332815015 M2P_SbmuPst_SysMinVolt_LvOn23 "系统所有低压在线的电柜的最小电芯电压所处SBMU编号";
CM_ SG_ 2332815015 M2P_CscPst_SysMinVolt_LvOn23 "系统所有低压在线的电柜的最小电芯电压所处CSC编号";
CM_ SG_ 2332815015 M2P_CellPst_SysMinVolt_LvOn23 "系统所有低压在线的电柜的最小电芯电压所处Cell编号";
CM_ SG_ 2332815015 M2P_SbmuPst_SysMinTemp_LvOn23 "系统所有低压在线的电柜的最小电芯温度所处SBMU编号";
CM_ SG_ 2332815015 M2P_CscPst_SysMinTemp_LvOn23 "系统所有低压在线的电柜的最小电芯温度所处CSC编号";
CM_ SG_ 2332815016 M2P_SbmuPst_SysMaxVolt_LvOn24 "系统所有低压在线的电柜的最大电芯电压所处SBMU编号";
CM_ SG_ 2332815016 M2P_CscPst_SysMaxVolt_LvOn24 "系统所有低压在线的电柜的最大电芯电压所处CSC编号";
CM_ SG_ 2332815016 M2P_CellPst_SysMaxVolt_LvOn24 "系统所有低压在线的电柜的最大电芯电压所处Cell编号";
CM_ SG_ 2332815016 M2P_SbmuPst_SysMinVolt_LvOn24 "系统所有低压在线的电柜的最小电芯电压所处SBMU编号";
CM_ SG_ 2332815016 M2P_CscPst_SysMinVolt_LvOn24 "系统所有低压在线的电柜的最小电芯电压所处CSC编号";
CM_ SG_ 2332815016 M2P_CellPst_SysMinVolt_LvOn24 "系统所有低压在线的电柜的最小电芯电压所处Cell编号";
CM_ SG_ 2332815016 M2P_SbmuPst_SysMinTemp_LvOn24 "系统所有低压在线的电柜的最小电芯温度所处SBMU编号";
CM_ SG_ 2332815016 M2P_CscPst_SysMinTemp_LvOn24 "系统所有低压在线的电柜的最小电芯温度所处CSC编号";
CM_ SG_ 2332815017 M2P_SbmuPst_SysMaxVolt_LvOn25 "系统所有低压在线的电柜的最大电芯电压所处SBMU编号";
CM_ SG_ 2332815017 M2P_CscPst_SysMaxVolt_LvOn25 "系统所有低压在线的电柜的最大电芯电压所处CSC编号";
CM_ SG_ 2332815017 M2P_CellPst_SysMaxVolt_LvOn25 "系统所有低压在线的电柜的最大电芯电压所处Cell编号";
CM_ SG_ 2332815017 M2P_SbmuPst_SysMinVolt_LvOn25 "系统所有低压在线的电柜的最小电芯电压所处SBMU编号";
CM_ SG_ 2332815017 M2P_CscPst_SysMinVolt_LvOn25 "系统所有低压在线的电柜的最小电芯电压所处CSC编号";
CM_ SG_ 2332815017 M2P_CellPst_SysMinVolt_LvOn25 "系统所有低压在线的电柜的最小电芯电压所处Cell编号";
CM_ SG_ 2332815017 M2P_SbmuPst_SysMinTemp_LvOn25 "系统所有低压在线的电柜的最小电芯温度所处SBMU编号";
CM_ SG_ 2332815017 M2P_CscPst_SysMinTemp_LvOn25 "系统所有低压在线的电柜的最小电芯温度所处CSC编号";
CM_ SG_ 2332815018 M2P_SbmuPst_SysMaxVolt_LvOn26 "系统所有低压在线的电柜的最大电芯电压所处SBMU编号";
CM_ SG_ 2332815018 M2P_CscPst_SysMaxVolt_LvOn26 "系统所有低压在线的电柜的最大电芯电压所处CSC编号";
CM_ SG_ 2332815018 M2P_CellPst_SysMaxVolt_LvOn26 "系统所有低压在线的电柜的最大电芯电压所处Cell编号";
CM_ SG_ 2332815018 M2P_SbmuPst_SysMinVolt_LvOn26 "系统所有低压在线的电柜的最小电芯电压所处SBMU编号";
CM_ SG_ 2332815018 M2P_CscPst_SysMinVolt_LvOn26 "系统所有低压在线的电柜的最小电芯电压所处CSC编号";
CM_ SG_ 2332815018 M2P_CellPst_SysMinVolt_LvOn26 "系统所有低压在线的电柜的最小电芯电压所处Cell编号";
CM_ SG_ 2332815018 M2P_SbmuPst_SysMinTemp_LvOn26 "系统所有低压在线的电柜的最小电芯温度所处SBMU编号";
CM_ SG_ 2332815018 M2P_CscPst_SysMinTemp_LvOn26 "系统所有低压在线的电柜的最小电芯温度所处CSC编号";
CM_ SG_ 2332815019 M2P_SbmuPst_SysMaxVolt_LvOn27 "系统所有低压在线的电柜的最大电芯电压所处SBMU编号";
CM_ SG_ 2332815019 M2P_CscPst_SysMaxVolt_LvOn27 "系统所有低压在线的电柜的最大电芯电压所处CSC编号";
CM_ SG_ 2332815019 M2P_CellPst_SysMaxVolt_LvOn27 "系统所有低压在线的电柜的最大电芯电压所处Cell编号";
CM_ SG_ 2332815019 M2P_SbmuPst_SysMinVolt_LvOn27 "系统所有低压在线的电柜的最小电芯电压所处SBMU编号";
CM_ SG_ 2332815019 M2P_CscPst_SysMinVolt_LvOn27 "系统所有低压在线的电柜的最小电芯电压所处CSC编号";
CM_ SG_ 2332815019 M2P_CellPst_SysMinVolt_LvOn27 "系统所有低压在线的电柜的最小电芯电压所处Cell编号";
CM_ SG_ 2332815019 M2P_SbmuPst_SysMinTemp_LvOn27 "系统所有低压在线的电柜的最小电芯温度所处SBMU编号";
CM_ SG_ 2332815019 M2P_CscPst_SysMinTemp_LvOn27 "系统所有低压在线的电柜的最小电芯温度所处CSC编号";
CM_ SG_ 2332815020 M2P_SbmuPst_SysMaxVolt_LvOn28 "系统所有低压在线的电柜的最大电芯电压所处SBMU编号";
CM_ SG_ 2332815020 M2P_CscPst_SysMaxVolt_LvOn28 "系统所有低压在线的电柜的最大电芯电压所处CSC编号";
CM_ SG_ 2332815020 M2P_CellPst_SysMaxVolt_LvOn28 "系统所有低压在线的电柜的最大电芯电压所处Cell编号";
CM_ SG_ 2332815020 M2P_SbmuPst_SysMinVolt_LvOn28 "系统所有低压在线的电柜的最小电芯电压所处SBMU编号";
CM_ SG_ 2332815020 M2P_CscPst_SysMinVolt_LvOn28 "系统所有低压在线的电柜的最小电芯电压所处CSC编号";
CM_ SG_ 2332815020 M2P_CellPst_SysMinVolt_LvOn28 "系统所有低压在线的电柜的最小电芯电压所处Cell编号";
CM_ SG_ 2332815020 M2P_SbmuPst_SysMinTemp_LvOn28 "系统所有低压在线的电柜的最小电芯温度所处SBMU编号";
CM_ SG_ 2332815020 M2P_CscPst_SysMinTemp_LvOn28 "系统所有低压在线的电柜的最小电芯温度所处CSC编号";
CM_ SG_ 2332815021 M2P_SbmuPst_SysMaxVolt_LvOn29 "系统所有低压在线的电柜的最大电芯电压所处SBMU编号";
CM_ SG_ 2332815021 M2P_CscPst_SysMaxVolt_LvOn29 "系统所有低压在线的电柜的最大电芯电压所处CSC编号";
CM_ SG_ 2332815021 M2P_CellPst_SysMaxVolt_LvOn29 "系统所有低压在线的电柜的最大电芯电压所处Cell编号";
CM_ SG_ 2332815021 M2P_SbmuPst_SysMinVolt_LvOn29 "系统所有低压在线的电柜的最小电芯电压所处SBMU编号";
CM_ SG_ 2332815021 M2P_CscPst_SysMinVolt_LvOn29 "系统所有低压在线的电柜的最小电芯电压所处CSC编号";
CM_ SG_ 2332815021 M2P_CellPst_SysMinVolt_LvOn29 "系统所有低压在线的电柜的最小电芯电压所处Cell编号";
CM_ SG_ 2332815021 M2P_SbmuPst_SysMinTemp_LvOn29 "系统所有低压在线的电柜的最小电芯温度所处SBMU编号";
CM_ SG_ 2332815021 M2P_CscPst_SysMinTemp_LvOn29 "系统所有低压在线的电柜的最小电芯温度所处CSC编号";
CM_ SG_ 2332815022 M2P_SbmuPst_SysMaxVolt_LvOn30 "系统所有低压在线的电柜的最大电芯电压所处SBMU编号";
CM_ SG_ 2332815022 M2P_CscPst_SysMaxVolt_LvOn30 "系统所有低压在线的电柜的最大电芯电压所处CSC编号";
CM_ SG_ 2332815022 M2P_CellPst_SysMaxVolt_LvOn30 "系统所有低压在线的电柜的最大电芯电压所处Cell编号";
CM_ SG_ 2332815022 M2P_SbmuPst_SysMinVolt_LvOn30 "系统所有低压在线的电柜的最小电芯电压所处SBMU编号";
CM_ SG_ 2332815022 M2P_CscPst_SysMinVolt_LvOn30 "系统所有低压在线的电柜的最小电芯电压所处CSC编号";
CM_ SG_ 2332815022 M2P_CellPst_SysMinVolt_LvOn30 "系统所有低压在线的电柜的最小电芯电压所处Cell编号";
CM_ SG_ 2332815022 M2P_SbmuPst_SysMinTemp_LvOn30 "系统所有低压在线的电柜的最小电芯温度所处SBMU编号";
CM_ SG_ 2332815022 M2P_CscPst_SysMinTemp_LvOn30 "系统所有低压在线的电柜的最小电芯温度所处CSC编号";
CM_ SG_ 2332815023 M2P_SbmuPst_SysMaxVolt_LvOn31 "系统所有低压在线的电柜的最大电芯电压所处SBMU编号";
CM_ SG_ 2332815023 M2P_CscPst_SysMaxVolt_LvOn31 "系统所有低压在线的电柜的最大电芯电压所处CSC编号";
CM_ SG_ 2332815023 M2P_CellPst_SysMaxVolt_LvOn31 "系统所有低压在线的电柜的最大电芯电压所处Cell编号";
CM_ SG_ 2332815023 M2P_SbmuPst_SysMinVolt_LvOn31 "系统所有低压在线的电柜的最小电芯电压所处SBMU编号";
CM_ SG_ 2332815023 M2P_CscPst_SysMinVolt_LvOn31 "系统所有低压在线的电柜的最小电芯电压所处CSC编号";
CM_ SG_ 2332815023 M2P_CellPst_SysMinVolt_LvOn31 "系统所有低压在线的电柜的最小电芯电压所处Cell编号";
CM_ SG_ 2332815023 M2P_SbmuPst_SysMinTemp_LvOn31 "系统所有低压在线的电柜的最小电芯温度所处SBMU编号";
CM_ SG_ 2332815023 M2P_CscPst_SysMinTemp_LvOn31 "系统所有低压在线的电柜的最小电芯温度所处CSC编号";
CM_ SG_ 2165538798 P2S_CMD2_data0 "PC发送给SBMU的存储数据清除指令密码1";
CM_ SG_ 2165538798 P2S_CMD2_data1 "PC发送给SBMU的存储数据清除指令密码2";
CM_ SG_ 2165538798 P2S_CMD2_data2 "PC发送给SBMU的存储数据清除指令密码3";
CM_ SG_ 2165538798 P2S_CMD2_data3 "PC发送给SBMU的存储数据清除指令密码4";
CM_ SG_ 2165538798 P2S_CMD2_data4 "PC发送给SBMU的存储数据清除指令";
CM_ SG_ 2165538798 P2S_CMD2_data5 "预留（不可用作其他功能）";
CM_ SG_ 2165538798 P2S_CMD2_data6 "预留（不可用作其他功能）";
CM_ SG_ 2165538798 P2S_CMD2_data7 "预留（不可用作其他功能）";
CM_ SG_ 2149100270 P2M_CMD6_data0 "PC发送给MBMU的存储数据清除指令码1";
CM_ SG_ 2149100270 P2M_CMD6_data1 "PC发送给MBMU的存储数据清除指令码2";
CM_ SG_ 2149100270 P2M_CMD6_data2 "PC发送给MBMU的存储数据清除指令码3";
CM_ SG_ 2149100270 P2M_CMD6_data3 "PC发送给MBMU的存储数据清除指令码4";
CM_ SG_ 2149100270 P2M_CMD6_data4 "PC发送给MBMU的存储数据清除指令码5";
CM_ SG_ 2149100270 P2M_CMD6_data5 "预留（不可用作其他功能）";
CM_ SG_ 2149100270 P2M_CMD6_data6 "预留（不可用作其他功能）";
CM_ SG_ 2149100270 P2M_CMD6_data7 "预留（不可用作其他功能）";
CM_ SG_ 2333736769 S2A_HisOTtimes_01 "电芯温度过高4级故障累积次数";
CM_ SG_ 2333736769 S2A_ChgtimeatLowtemp_01 "低温下累积充电时间";
CM_ SG_ 2333736770 S2A_HisOTtimes_02 "电芯温度过高4级故障累积次数";
CM_ SG_ 2333736770 S2A_ChgtimeatLowtemp_02 "低温下累积充电时间";
CM_ SG_ 2333736771 S2A_HisOTtimes_03 "电芯温度过高4级故障累积次数";
CM_ SG_ 2333736771 S2A_ChgtimeatLowtemp_03 "低温下累积充电时间";
CM_ SG_ 2333736772 S2A_HisOTtimes_04 "电芯温度过高4级故障累积次数";
CM_ SG_ 2333736772 S2A_ChgtimeatLowtemp_04 "低温下累积充电时间";
CM_ SG_ 2333736773 S2A_HisOTtimes_05 "电芯温度过高4级故障累积次数";
CM_ SG_ 2333736773 S2A_ChgtimeatLowtemp_05 "低温下累积充电时间";
CM_ SG_ 2333736774 S2A_HisOTtimes_06 "电芯温度过高4级故障累积次数";
CM_ SG_ 2333736774 S2A_ChgtimeatLowtemp_06 "低温下累积充电时间";
CM_ SG_ 2333736775 S2A_HisOTtimes_07 "电芯温度过高4级故障累积次数";
CM_ SG_ 2333736775 S2A_ChgtimeatLowtemp_07 "低温下累积充电时间";
CM_ SG_ 2333736776 S2A_HisOTtimes_08 "电芯温度过高4级故障累积次数";
CM_ SG_ 2333736776 S2A_ChgtimeatLowtemp_08 "低温下累积充电时间";
CM_ SG_ 2333736777 S2A_HisOTtimes_09 "电芯温度过高4级故障累积次数";
CM_ SG_ 2333736777 S2A_ChgtimeatLowtemp_09 "低温下累积充电时间";
CM_ SG_ 2333736778 S2A_HisOTtimes_10 "电芯温度过高4级故障累积次数";
CM_ SG_ 2333736778 S2A_ChgtimeatLowtemp_10 "低温下累积充电时间";
CM_ SG_ 2333736779 S2A_HisOTtimes_11 "电芯温度过高4级故障累积次数";
CM_ SG_ 2333736779 S2A_ChgtimeatLowtemp_11 "低温下累积充电时间";
CM_ SG_ 2333736780 S2A_HisOTtimes_12 "电芯温度过高4级故障累积次数";
CM_ SG_ 2333736780 S2A_ChgtimeatLowtemp_12 "低温下累积充电时间";
CM_ SG_ 2333736781 S2A_HisOTtimes_13 "电芯温度过高4级故障累积次数";
CM_ SG_ 2333736781 S2A_ChgtimeatLowtemp_13 "低温下累积充电时间";
CM_ SG_ 2333736782 S2A_HisOTtimes_14 "电芯温度过高4级故障累积次数";
CM_ SG_ 2333736782 S2A_ChgtimeatLowtemp_14 "低温下累积充电时间";
CM_ SG_ 2333736783 S2A_HisOTtimes_15 "电芯温度过高4级故障累积次数";
CM_ SG_ 2333736783 S2A_ChgtimeatLowtemp_15 "低温下累积充电时间";
CM_ SG_ 2333736784 S2A_HisOTtimes_16 "电芯温度过高4级故障累积次数";
CM_ SG_ 2333736784 S2A_ChgtimeatLowtemp_16 "低温下累积充电时间";
CM_ SG_ 2333736785 S2A_HisOTtimes_17 "电芯温度过高4级故障累积次数";
CM_ SG_ 2333736785 S2A_ChgtimeatLowtemp_17 "低温下累积充电时间";
CM_ SG_ 2333736786 S2A_HisOTtimes_18 "电芯温度过高4级故障累积次数";
CM_ SG_ 2333736786 S2A_ChgtimeatLowtemp_18 "低温下累积充电时间";
CM_ SG_ 2333736787 S2A_HisOTtimes_19 "电芯温度过高4级故障累积次数";
CM_ SG_ 2333736787 S2A_ChgtimeatLowtemp_19 "低温下累积充电时间";
CM_ SG_ 2333736788 S2A_HisOTtimes_20 "电芯温度过高4级故障累积次数";
CM_ SG_ 2333736788 S2A_ChgtimeatLowtemp_20 "低温下累积充电时间";
CM_ SG_ 2333736789 S2A_HisOTtimes_21 "电芯温度过高4级故障累积次数";
CM_ SG_ 2333736789 S2A_ChgtimeatLowtemp_21 "低温下累积充电时间";
CM_ SG_ 2333736790 S2A_HisOTtimes_22 "电芯温度过高4级故障累积次数";
CM_ SG_ 2333736790 S2A_ChgtimeatLowtemp_22 "低温下累积充电时间";
CM_ SG_ 2333736791 S2A_HisOTtimes_23 "电芯温度过高4级故障累积次数";
CM_ SG_ 2333736791 S2A_ChgtimeatLowtemp_23 "低温下累积充电时间";
CM_ SG_ 2333736792 S2A_HisOTtimes_24 "电芯温度过高4级故障累积次数";
CM_ SG_ 2333736792 S2A_ChgtimeatLowtemp_24 "低温下累积充电时间";
CM_ SG_ 2333736793 S2A_HisOTtimes_25 "电芯温度过高4级故障累积次数";
CM_ SG_ 2333736793 S2A_ChgtimeatLowtemp_25 "低温下累积充电时间";
CM_ SG_ 2333736794 S2A_HisOTtimes_26 "电芯温度过高4级故障累积次数";
CM_ SG_ 2333736794 S2A_ChgtimeatLowtemp_26 "低温下累积充电时间";
CM_ SG_ 2333736795 S2A_HisOTtimes_27 "电芯温度过高4级故障累积次数";
CM_ SG_ 2333736795 S2A_ChgtimeatLowtemp_27 "低温下累积充电时间";
CM_ SG_ 2333736796 S2A_HisOTtimes_28 "电芯温度过高4级故障累积次数";
CM_ SG_ 2333736796 S2A_ChgtimeatLowtemp_28 "低温下累积充电时间";
CM_ SG_ 2333736797 S2A_HisOTtimes_29 "电芯温度过高4级故障累积次数";
CM_ SG_ 2333736797 S2A_ChgtimeatLowtemp_29 "低温下累积充电时间";
CM_ SG_ 2333736798 S2A_HisOTtimes_30 "电芯温度过高4级故障累积次数";
CM_ SG_ 2333736798 S2A_ChgtimeatLowtemp_30 "低温下累积充电时间";
CM_ SG_ 2333736799 S2A_HisOTtimes_31 "电芯温度过高4级故障累积次数";
CM_ SG_ 2333736799 S2A_ChgtimeatLowtemp_31 "低温下累积充电时间";
CM_ SG_ 2333736800 S2A_HisOTtimes_32 "电芯温度过高4级故障累积次数";
CM_ SG_ 2333736800 S2A_ChgtimeatLowtemp_32 "低温下累积充电时间";
CM_ SG_ 2333736801 S2A_HisOTtimes_33 "电芯温度过高4级故障累积次数";
CM_ SG_ 2333736801 S2A_ChgtimeatLowtemp_33 "低温下累积充电时间";
CM_ SG_ 2333736802 S2A_HisOTtimes_34 "电芯温度过高4级故障累积次数";
CM_ SG_ 2333736802 S2A_ChgtimeatLowtemp_34 "低温下累积充电时间";
CM_ SG_ 2333736803 S2A_HisOTtimes_35 "电芯温度过高4级故障累积次数";
CM_ SG_ 2333736803 S2A_ChgtimeatLowtemp_35 "低温下累积充电时间";
CM_ SG_ 2333736804 S2A_HisOTtimes_36 "电芯温度过高4级故障累积次数";
CM_ SG_ 2333736804 S2A_ChgtimeatLowtemp_36 "低温下累积充电时间";
CM_ SG_ 2333736805 S2A_HisOTtimes_37 "电芯温度过高4级故障累积次数";
CM_ SG_ 2333736805 S2A_ChgtimeatLowtemp_37 "低温下累积充电时间";
CM_ SG_ 2333736806 S2A_HisOTtimes_38 "电芯温度过高4级故障累积次数";
CM_ SG_ 2333736806 S2A_ChgtimeatLowtemp_38 "低温下累积充电时间";
CM_ SG_ 2333736807 S2A_HisOTtimes_39 "电芯温度过高4级故障累积次数";
CM_ SG_ 2333736807 S2A_ChgtimeatLowtemp_39 "低温下累积充电时间";
CM_ SG_ 2333736808 S2A_HisOTtimes_40 "电芯温度过高4级故障累积次数";
CM_ SG_ 2333736808 S2A_ChgtimeatLowtemp_40 "低温下累积充电时间";
CM_ SG_ 2333736809 S2A_HisOTtimes_41 "电芯温度过高4级故障累积次数";
CM_ SG_ 2333736809 S2A_ChgtimeatLowtemp_41 "低温下累积充电时间";
CM_ SG_ 2333736810 S2A_HisOTtimes_42 "电芯温度过高4级故障累积次数";
CM_ SG_ 2333736810 S2A_ChgtimeatLowtemp_42 "低温下累积充电时间";
CM_ SG_ 2333736811 S2A_HisOTtimes_43 "电芯温度过高4级故障累积次数";
CM_ SG_ 2333736811 S2A_ChgtimeatLowtemp_43 "低温下累积充电时间";
CM_ SG_ 2333736812 S2A_HisOTtimes_44 "电芯温度过高4级故障累积次数";
CM_ SG_ 2333736812 S2A_ChgtimeatLowtemp_44 "低温下累积充电时间";
CM_ SG_ 2333736813 S2A_HisOTtimes_45 "电芯温度过高4级故障累积次数";
CM_ SG_ 2333736813 S2A_ChgtimeatLowtemp_45 "低温下累积充电时间";
CM_ SG_ 2333736814 S2A_HisOTtimes_46 "电芯温度过高4级故障累积次数";
CM_ SG_ 2333736814 S2A_ChgtimeatLowtemp_46 "低温下累积充电时间";
CM_ SG_ 2333736815 S2A_HisOTtimes_47 "电芯温度过高4级故障累积次数";
CM_ SG_ 2333736815 S2A_ChgtimeatLowtemp_47 "低温下累积充电时间";
CM_ SG_ 2333736816 S2A_HisOTtimes_48 "电芯温度过高4级故障累积次数";
CM_ SG_ 2333736816 S2A_ChgtimeatLowtemp_48 "低温下累积充电时间";
CM_ SG_ 2333736817 S2A_HisOTtimes_49 "电芯温度过高4级故障累积次数";
CM_ SG_ 2333736817 S2A_ChgtimeatLowtemp_49 "低温下累积充电时间";
CM_ SG_ 2333736818 S2A_HisOTtimes_50 "电芯温度过高4级故障累积次数";
CM_ SG_ 2333736818 S2A_ChgtimeatLowtemp_50 "低温下累积充电时间";
CM_ SG_ 2333736819 S2A_HisOTtimes_51 "电芯温度过高4级故障累积次数";
CM_ SG_ 2333736819 S2A_ChgtimeatLowtemp_51 "低温下累积充电时间";
CM_ SG_ 2333736820 S2A_HisOTtimes_52 "电芯温度过高4级故障累积次数";
CM_ SG_ 2333736820 S2A_ChgtimeatLowtemp_52 "低温下累积充电时间";
CM_ SG_ 2333736821 S2A_HisOTtimes_53 "电芯温度过高4级故障累积次数";
CM_ SG_ 2333736821 S2A_ChgtimeatLowtemp_53 "低温下累积充电时间";
CM_ SG_ 2333736822 S2A_HisOTtimes_54 "电芯温度过高4级故障累积次数";
CM_ SG_ 2333736822 S2A_ChgtimeatLowtemp_54 "低温下累积充电时间";
CM_ SG_ 2333736823 S2A_HisOTtimes_55 "电芯温度过高4级故障累积次数";
CM_ SG_ 2333736823 S2A_ChgtimeatLowtemp_55 "低温下累积充电时间";
CM_ SG_ 2333736824 S2A_HisOTtimes_56 "电芯温度过高4级故障累积次数";
CM_ SG_ 2333736824 S2A_ChgtimeatLowtemp_56 "低温下累积充电时间";
CM_ SG_ 2333736825 S2A_HisOTtimes_57 "电芯温度过高4级故障累积次数";
CM_ SG_ 2333736825 S2A_ChgtimeatLowtemp_57 "低温下累积充电时间";
CM_ SG_ 2333736826 S2A_HisOTtimes_58 "电芯温度过高4级故障累积次数";
CM_ SG_ 2333736826 S2A_ChgtimeatLowtemp_58 "低温下累积充电时间";
CM_ SG_ 2333736827 S2A_HisOTtimes_59 "电芯温度过高4级故障累积次数";
CM_ SG_ 2333736827 S2A_ChgtimeatLowtemp_59 "低温下累积充电时间";
CM_ SG_ 2333736828 S2A_HisOTtimes_60 "电芯温度过高4级故障累积次数";
CM_ SG_ 2333736828 S2A_ChgtimeatLowtemp_60 "低温下累积充电时间";
CM_ SG_ 2333736829 S2A_HisOTtimes_61 "电芯温度过高4级故障累积次数";
CM_ SG_ 2333736829 S2A_ChgtimeatLowtemp_61 "低温下累积充电时间";
CM_ SG_ 2333736830 S2A_HisOTtimes_62 "电芯温度过高4级故障累积次数";
CM_ SG_ 2333736830 S2A_ChgtimeatLowtemp_62 "低温下累积充电时间";
CM_ SG_ 2333736831 S2A_HisOTtimes_63 "电芯温度过高4级故障累积次数";
CM_ SG_ 2333736831 S2A_ChgtimeatLowtemp_63 "低温下累积充电时间";
CM_ SG_ 2334195521 S2A_DurationatLowtemp_01 "低温下累积时间";
CM_ SG_ 2334195521 S2A_DurationatHightemp_01 "高温下累积时间";
CM_ SG_ 2334195522 S2A_DurationatLowtemp_02 "低温下累积时间";
CM_ SG_ 2334195522 S2A_DurationatHightemp_02 "高温下累积时间";
CM_ SG_ 2334195523 S2A_DurationatLowtemp_03 "低温下累积时间";
CM_ SG_ 2334195523 S2A_DurationatHightemp_03 "高温下累积时间";
CM_ SG_ 2334195524 S2A_DurationatLowtemp_04 "低温下累积时间";
CM_ SG_ 2334195524 S2A_DurationatHightemp_04 "高温下累积时间";
CM_ SG_ 2334195525 S2A_DurationatLowtemp_05 "低温下累积时间";
CM_ SG_ 2334195525 S2A_DurationatHightemp_05 "高温下累积时间";
CM_ SG_ 2334195526 S2A_DurationatLowtemp_06 "低温下累积时间";
CM_ SG_ 2334195526 S2A_DurationatHightemp_06 "高温下累积时间";
CM_ SG_ 2334195527 S2A_DurationatLowtemp_07 "低温下累积时间";
CM_ SG_ 2334195527 S2A_DurationatHightemp_07 "高温下累积时间";
CM_ SG_ 2334195528 S2A_DurationatLowtemp_08 "低温下累积时间";
CM_ SG_ 2334195528 S2A_DurationatHightemp_08 "高温下累积时间";
CM_ SG_ 2334195529 S2A_DurationatLowtemp_09 "低温下累积时间";
CM_ SG_ 2334195529 S2A_DurationatHightemp_09 "高温下累积时间";
CM_ SG_ 2334195530 S2A_DurationatLowtemp_10 "低温下累积时间";
CM_ SG_ 2334195530 S2A_DurationatHightemp_10 "高温下累积时间";
CM_ SG_ 2334195531 S2A_DurationatLowtemp_11 "低温下累积时间";
CM_ SG_ 2334195531 S2A_DurationatHightemp_11 "高温下累积时间";
CM_ SG_ 2334195532 S2A_DurationatLowtemp_12 "低温下累积时间";
CM_ SG_ 2334195532 S2A_DurationatHightemp_12 "高温下累积时间";
CM_ SG_ 2334195533 S2A_DurationatLowtemp_13 "低温下累积时间";
CM_ SG_ 2334195533 S2A_DurationatHightemp_13 "高温下累积时间";
CM_ SG_ 2334195534 S2A_DurationatLowtemp_14 "低温下累积时间";
CM_ SG_ 2334195534 S2A_DurationatHightemp_14 "高温下累积时间";
CM_ SG_ 2334195535 S2A_DurationatLowtemp_15 "低温下累积时间";
CM_ SG_ 2334195535 S2A_DurationatHightemp_15 "高温下累积时间";
CM_ SG_ 2334195536 S2A_DurationatLowtemp_16 "低温下累积时间";
CM_ SG_ 2334195536 S2A_DurationatHightemp_16 "高温下累积时间";
CM_ SG_ 2334195537 S2A_DurationatLowtemp_17 "低温下累积时间";
CM_ SG_ 2334195537 S2A_DurationatHightemp_17 "高温下累积时间";
CM_ SG_ 2334195538 S2A_DurationatLowtemp_18 "低温下累积时间";
CM_ SG_ 2334195538 S2A_DurationatHightemp_18 "高温下累积时间";
CM_ SG_ 2334195539 S2A_DurationatLowtemp_19 "低温下累积时间";
CM_ SG_ 2334195539 S2A_DurationatHightemp_19 "高温下累积时间";
CM_ SG_ 2334195540 S2A_DurationatLowtemp_20 "低温下累积时间";
CM_ SG_ 2334195540 S2A_DurationatHightemp_20 "高温下累积时间";
CM_ SG_ 2334195541 S2A_DurationatLowtemp_21 "低温下累积时间";
CM_ SG_ 2334195541 S2A_DurationatHightemp_21 "高温下累积时间";
CM_ SG_ 2334195542 S2A_DurationatLowtemp_22 "低温下累积时间";
CM_ SG_ 2334195542 S2A_DurationatHightemp_22 "高温下累积时间";
CM_ SG_ 2334195543 S2A_DurationatLowtemp_23 "低温下累积时间";
CM_ SG_ 2334195543 S2A_DurationatHightemp_23 "高温下累积时间";
CM_ SG_ 2334195544 S2A_DurationatLowtemp_24 "低温下累积时间";
CM_ SG_ 2334195544 S2A_DurationatHightemp_24 "高温下累积时间";
CM_ SG_ 2334195545 S2A_DurationatLowtemp_25 "低温下累积时间";
CM_ SG_ 2334195545 S2A_DurationatHightemp_25 "高温下累积时间";
CM_ SG_ 2334195546 S2A_DurationatLowtemp_26 "低温下累积时间";
CM_ SG_ 2334195546 S2A_DurationatHightemp_26 "高温下累积时间";
CM_ SG_ 2334195547 S2A_DurationatLowtemp_27 "低温下累积时间";
CM_ SG_ 2334195547 S2A_DurationatHightemp_27 "高温下累积时间";
CM_ SG_ 2334195548 S2A_DurationatLowtemp_28 "低温下累积时间";
CM_ SG_ 2334195548 S2A_DurationatHightemp_28 "高温下累积时间";
CM_ SG_ 2334195549 S2A_DurationatLowtemp_29 "低温下累积时间";
CM_ SG_ 2334195549 S2A_DurationatHightemp_29 "高温下累积时间";
CM_ SG_ 2334195550 S2A_DurationatLowtemp_30 "低温下累积时间";
CM_ SG_ 2334195550 S2A_DurationatHightemp_30 "高温下累积时间";
CM_ SG_ 2334195551 S2A_DurationatLowtemp_31 "低温下累积时间";
CM_ SG_ 2334195551 S2A_DurationatHightemp_31 "高温下累积时间";
CM_ SG_ 2334195552 S2A_DurationatLowtemp_32 "低温下累积时间";
CM_ SG_ 2334195552 S2A_DurationatHightemp_32 "高温下累积时间";
CM_ SG_ 2334195553 S2A_DurationatLowtemp_33 "低温下累积时间";
CM_ SG_ 2334195553 S2A_DurationatHightemp_33 "高温下累积时间";
CM_ SG_ 2334195554 S2A_DurationatLowtemp_34 "低温下累积时间";
CM_ SG_ 2334195554 S2A_DurationatHightemp_34 "高温下累积时间";
CM_ SG_ 2334195555 S2A_DurationatLowtemp_35 "低温下累积时间";
CM_ SG_ 2334195555 S2A_DurationatHightemp_35 "高温下累积时间";
CM_ SG_ 2334195556 S2A_DurationatLowtemp_36 "低温下累积时间";
CM_ SG_ 2334195556 S2A_DurationatHightemp_36 "高温下累积时间";
CM_ SG_ 2334195557 S2A_DurationatLowtemp_37 "低温下累积时间";
CM_ SG_ 2334195557 S2A_DurationatHightemp_37 "高温下累积时间";
CM_ SG_ 2334195558 S2A_DurationatLowtemp_38 "低温下累积时间";
CM_ SG_ 2334195558 S2A_DurationatHightemp_38 "高温下累积时间";
CM_ SG_ 2334195559 S2A_DurationatLowtemp_39 "低温下累积时间";
CM_ SG_ 2334195559 S2A_DurationatHightemp_39 "高温下累积时间";
CM_ SG_ 2334195560 S2A_DurationatLowtemp_40 "低温下累积时间";
CM_ SG_ 2334195560 S2A_DurationatHightemp_40 "高温下累积时间";
CM_ SG_ 2334195561 S2A_DurationatLowtemp_41 "低温下累积时间";
CM_ SG_ 2334195561 S2A_DurationatHightemp_41 "高温下累积时间";
CM_ SG_ 2334195562 S2A_DurationatLowtemp_42 "低温下累积时间";
CM_ SG_ 2334195562 S2A_DurationatHightemp_42 "高温下累积时间";
CM_ SG_ 2334195563 S2A_DurationatLowtemp_43 "低温下累积时间";
CM_ SG_ 2334195563 S2A_DurationatHightemp_43 "高温下累积时间";
CM_ SG_ 2334195564 S2A_DurationatLowtemp_44 "低温下累积时间";
CM_ SG_ 2334195564 S2A_DurationatHightemp_44 "高温下累积时间";
CM_ SG_ 2334195565 S2A_DurationatLowtemp_45 "低温下累积时间";
CM_ SG_ 2334195565 S2A_DurationatHightemp_45 "高温下累积时间";
CM_ SG_ 2334195566 S2A_DurationatLowtemp_46 "低温下累积时间";
CM_ SG_ 2334195566 S2A_DurationatHightemp_46 "高温下累积时间";
CM_ SG_ 2334195567 S2A_DurationatLowtemp_47 "低温下累积时间";
CM_ SG_ 2334195567 S2A_DurationatHightemp_47 "高温下累积时间";
CM_ SG_ 2334195568 S2A_DurationatLowtemp_48 "低温下累积时间";
CM_ SG_ 2334195568 S2A_DurationatHightemp_48 "高温下累积时间";
CM_ SG_ 2334195569 S2A_DurationatLowtemp_49 "低温下累积时间";
CM_ SG_ 2334195569 S2A_DurationatHightemp_49 "高温下累积时间";
CM_ SG_ 2334195570 S2A_DurationatLowtemp_50 "低温下累积时间";
CM_ SG_ 2334195570 S2A_DurationatHightemp_50 "高温下累积时间";
CM_ SG_ 2334195571 S2A_DurationatLowtemp_51 "低温下累积时间";
CM_ SG_ 2334195571 S2A_DurationatHightemp_51 "高温下累积时间";
CM_ SG_ 2334195572 S2A_DurationatLowtemp_52 "低温下累积时间";
CM_ SG_ 2334195572 S2A_DurationatHightemp_52 "高温下累积时间";
CM_ SG_ 2334195573 S2A_DurationatLowtemp_53 "低温下累积时间";
CM_ SG_ 2334195573 S2A_DurationatHightemp_53 "高温下累积时间";
CM_ SG_ 2334195574 S2A_DurationatLowtemp_54 "低温下累积时间";
CM_ SG_ 2334195574 S2A_DurationatHightemp_54 "高温下累积时间";
CM_ SG_ 2334195575 S2A_DurationatLowtemp_55 "低温下累积时间";
CM_ SG_ 2334195575 S2A_DurationatHightemp_55 "高温下累积时间";
CM_ SG_ 2334195576 S2A_DurationatLowtemp_56 "低温下累积时间";
CM_ SG_ 2334195576 S2A_DurationatHightemp_56 "高温下累积时间";
CM_ SG_ 2334195577 S2A_DurationatLowtemp_57 "低温下累积时间";
CM_ SG_ 2334195577 S2A_DurationatHightemp_57 "高温下累积时间";
CM_ SG_ 2334195578 S2A_DurationatLowtemp_58 "低温下累积时间";
CM_ SG_ 2334195578 S2A_DurationatHightemp_58 "高温下累积时间";
CM_ SG_ 2334195579 S2A_DurationatLowtemp_59 "低温下累积时间";
CM_ SG_ 2334195579 S2A_DurationatHightemp_59 "高温下累积时间";
CM_ SG_ 2334195580 S2A_DurationatLowtemp_60 "低温下累积时间";
CM_ SG_ 2334195580 S2A_DurationatHightemp_60 "高温下累积时间";
CM_ SG_ 2334195581 S2A_DurationatLowtemp_61 "低温下累积时间";
CM_ SG_ 2334195581 S2A_DurationatHightemp_61 "高温下累积时间";
CM_ SG_ 2334195582 S2A_DurationatLowtemp_62 "低温下累积时间";
CM_ SG_ 2334195582 S2A_DurationatHightemp_62 "高温下累积时间";
CM_ SG_ 2334195583 S2A_DurationatLowtemp_63 "低温下累积时间";
CM_ SG_ 2334195583 S2A_DurationatHightemp_63 "高温下累积时间";
CM_ SG_ 2334261057 S2A_ChgtimesatHightemp_01 "高温下累积充电时间";
CM_ SG_ 2334261057 S2A_DisChgtimesatHightemp_01 "高温下累积放电时间";
CM_ SG_ 2334261058 S2A_ChgtimesatHightemp_02 "高温下累积充电时间";
CM_ SG_ 2334261058 S2A_DisChgtimesatHightemp_02 "高温下累积放电时间";
CM_ SG_ 2334261059 S2A_ChgtimesatHightemp_03 "高温下累积充电时间";
CM_ SG_ 2334261059 S2A_DisChgtimesatHightemp_03 "高温下累积放电时间";
CM_ SG_ 2334261060 S2A_ChgtimesatHightemp_04 "高温下累积充电时间";
CM_ SG_ 2334261060 S2A_DisChgtimesatHightemp_04 "高温下累积放电时间";
CM_ SG_ 2334261061 S2A_ChgtimesatHightemp_05 "高温下累积充电时间";
CM_ SG_ 2334261061 S2A_DisChgtimesatHightemp_05 "高温下累积放电时间";
CM_ SG_ 2334261062 S2A_ChgtimesatHightemp_06 "高温下累积充电时间";
CM_ SG_ 2334261062 S2A_DisChgtimesatHightemp_06 "高温下累积放电时间";
CM_ SG_ 2334261063 S2A_ChgtimesatHightemp_07 "高温下累积充电时间";
CM_ SG_ 2334261063 S2A_DisChgtimesatHightemp_07 "高温下累积放电时间";
CM_ SG_ 2334261064 S2A_ChgtimesatHightemp_08 "高温下累积充电时间";
CM_ SG_ 2334261064 S2A_DisChgtimesatHightemp_08 "高温下累积放电时间";
CM_ SG_ 2334261065 S2A_ChgtimesatHightemp_09 "高温下累积充电时间";
CM_ SG_ 2334261065 S2A_DisChgtimesatHightemp_09 "高温下累积放电时间";
CM_ SG_ 2334261066 S2A_ChgtimesatHightemp_10 "高温下累积充电时间";
CM_ SG_ 2334261066 S2A_DisChgtimesatHightemp_10 "高温下累积放电时间";
CM_ SG_ 2334261067 S2A_ChgtimesatHightemp_11 "高温下累积充电时间";
CM_ SG_ 2334261067 S2A_DisChgtimesatHightemp_11 "高温下累积放电时间";
CM_ SG_ 2334261068 S2A_ChgtimesatHightemp_12 "高温下累积充电时间";
CM_ SG_ 2334261068 S2A_DisChgtimesatHightemp_12 "高温下累积放电时间";
CM_ SG_ 2334261069 S2A_ChgtimesatHightemp_13 "高温下累积充电时间";
CM_ SG_ 2334261069 S2A_DisChgtimesatHightemp_13 "高温下累积放电时间";
CM_ SG_ 2334261070 S2A_ChgtimesatHightemp_14 "高温下累积充电时间";
CM_ SG_ 2334261070 S2A_DisChgtimesatHightemp_14 "高温下累积放电时间";
CM_ SG_ 2334261071 S2A_ChgtimesatHightemp_15 "高温下累积充电时间";
CM_ SG_ 2334261071 S2A_DisChgtimesatHightemp_15 "高温下累积放电时间";
CM_ SG_ 2334261072 S2A_ChgtimesatHightemp_16 "高温下累积充电时间";
CM_ SG_ 2334261072 S2A_DisChgtimesatHightemp_16 "高温下累积放电时间";
CM_ SG_ 2334261073 S2A_ChgtimesatHightemp_17 "高温下累积充电时间";
CM_ SG_ 2334261073 S2A_DisChgtimesatHightemp_17 "高温下累积放电时间";
CM_ SG_ 2334261074 S2A_ChgtimesatHightemp_18 "高温下累积充电时间";
CM_ SG_ 2334261074 S2A_DisChgtimesatHightemp_18 "高温下累积放电时间";
CM_ SG_ 2334261075 S2A_ChgtimesatHightemp_19 "高温下累积充电时间";
CM_ SG_ 2334261075 S2A_DisChgtimesatHightemp_19 "高温下累积放电时间";
CM_ SG_ 2334261076 S2A_ChgtimesatHightemp_20 "高温下累积充电时间";
CM_ SG_ 2334261076 S2A_DisChgtimesatHightemp_20 "高温下累积放电时间";
CM_ SG_ 2334261077 S2A_ChgtimesatHightemp_21 "高温下累积充电时间";
CM_ SG_ 2334261077 S2A_DisChgtimesatHightemp_21 "高温下累积放电时间";
CM_ SG_ 2334261078 S2A_ChgtimesatHightemp_22 "高温下累积充电时间";
CM_ SG_ 2334261078 S2A_DisChgtimesatHightemp_22 "高温下累积放电时间";
CM_ SG_ 2334261079 S2A_ChgtimesatHightemp_23 "高温下累积充电时间";
CM_ SG_ 2334261079 S2A_DisChgtimesatHightemp_23 "高温下累积放电时间";
CM_ SG_ 2334261080 S2A_ChgtimesatHightemp_24 "高温下累积充电时间";
CM_ SG_ 2334261080 S2A_DisChgtimesatHightemp_24 "高温下累积放电时间";
CM_ SG_ 2334261081 S2A_ChgtimesatHightemp_25 "高温下累积充电时间";
CM_ SG_ 2334261081 S2A_DisChgtimesatHightemp_25 "高温下累积放电时间";
CM_ SG_ 2334261082 S2A_ChgtimesatHightemp_26 "高温下累积充电时间";
CM_ SG_ 2334261082 S2A_DisChgtimesatHightemp_26 "高温下累积放电时间";
CM_ SG_ 2334261083 S2A_ChgtimesatHightemp_27 "高温下累积充电时间";
CM_ SG_ 2334261083 S2A_DisChgtimesatHightemp_27 "高温下累积放电时间";
CM_ SG_ 2334261084 S2A_ChgtimesatHightemp_28 "高温下累积充电时间";
CM_ SG_ 2334261084 S2A_DisChgtimesatHightemp_28 "高温下累积放电时间";
CM_ SG_ 2334261085 S2A_ChgtimesatHightemp_29 "高温下累积充电时间";
CM_ SG_ 2334261085 S2A_DisChgtimesatHightemp_29 "高温下累积放电时间";
CM_ SG_ 2334261086 S2A_ChgtimesatHightemp_30 "高温下累积充电时间";
CM_ SG_ 2334261086 S2A_DisChgtimesatHightemp_30 "高温下累积放电时间";
CM_ SG_ 2334261087 S2A_ChgtimesatHightemp_31 "高温下累积充电时间";
CM_ SG_ 2334261087 S2A_DisChgtimesatHightemp_31 "高温下累积放电时间";
CM_ SG_ 2334261088 S2A_ChgtimesatHightemp_32 "高温下累积充电时间";
CM_ SG_ 2334261088 S2A_DisChgtimesatHightemp_32 "高温下累积放电时间";
CM_ SG_ 2334261089 S2A_ChgtimesatHightemp_33 "高温下累积充电时间";
CM_ SG_ 2334261089 S2A_DisChgtimesatHightemp_33 "高温下累积放电时间";
CM_ SG_ 2334261090 S2A_ChgtimesatHightemp_34 "高温下累积充电时间";
CM_ SG_ 2334261090 S2A_DisChgtimesatHightemp_34 "高温下累积放电时间";
CM_ SG_ 2334261091 S2A_ChgtimesatHightemp_35 "高温下累积充电时间";
CM_ SG_ 2334261091 S2A_DisChgtimesatHightemp_35 "高温下累积放电时间";
CM_ SG_ 2334261092 S2A_ChgtimesatHightemp_36 "高温下累积充电时间";
CM_ SG_ 2334261092 S2A_DisChgtimesatHightemp_36 "高温下累积放电时间";
CM_ SG_ 2334261093 S2A_ChgtimesatHightemp_37 "高温下累积充电时间";
CM_ SG_ 2334261093 S2A_DisChgtimesatHightemp_37 "高温下累积放电时间";
CM_ SG_ 2334261094 S2A_ChgtimesatHightemp_38 "高温下累积充电时间";
CM_ SG_ 2334261094 S2A_DisChgtimesatHightemp_38 "高温下累积放电时间";
CM_ SG_ 2334261095 S2A_ChgtimesatHightemp_39 "高温下累积充电时间";
CM_ SG_ 2334261095 S2A_DisChgtimesatHightemp_39 "高温下累积放电时间";
CM_ SG_ 2334261096 S2A_ChgtimesatHightemp_40 "高温下累积充电时间";
CM_ SG_ 2334261096 S2A_DisChgtimesatHightemp_40 "高温下累积放电时间";
CM_ SG_ 2334261097 S2A_ChgtimesatHightemp_41 "高温下累积充电时间";
CM_ SG_ 2334261097 S2A_DisChgtimesatHightemp_41 "高温下累积放电时间";
CM_ SG_ 2334261098 S2A_ChgtimesatHightemp_42 "高温下累积充电时间";
CM_ SG_ 2334261098 S2A_DisChgtimesatHightemp_42 "高温下累积放电时间";
CM_ SG_ 2334261099 S2A_ChgtimesatHightemp_43 "高温下累积充电时间";
CM_ SG_ 2334261099 S2A_DisChgtimesatHightemp_43 "高温下累积放电时间";
CM_ SG_ 2334261100 S2A_ChgtimesatHightemp_44 "高温下累积充电时间";
CM_ SG_ 2334261100 S2A_DisChgtimesatHightemp_44 "高温下累积放电时间";
CM_ SG_ 2334261101 S2A_ChgtimesatHightemp_45 "高温下累积充电时间";
CM_ SG_ 2334261101 S2A_DisChgtimesatHightemp_45 "高温下累积放电时间";
CM_ SG_ 2334261102 S2A_ChgtimesatHightemp_46 "高温下累积充电时间";
CM_ SG_ 2334261102 S2A_DisChgtimesatHightemp_46 "高温下累积放电时间";
CM_ SG_ 2334261103 S2A_ChgtimesatHightemp_47 "高温下累积充电时间";
CM_ SG_ 2334261103 S2A_DisChgtimesatHightemp_47 "高温下累积放电时间";
CM_ SG_ 2334261104 S2A_ChgtimesatHightemp_48 "高温下累积充电时间";
CM_ SG_ 2334261104 S2A_DisChgtimesatHightemp_48 "高温下累积放电时间";
CM_ SG_ 2334261105 S2A_ChgtimesatHightemp_49 "高温下累积充电时间";
CM_ SG_ 2334261105 S2A_DisChgtimesatHightemp_49 "高温下累积放电时间";
CM_ SG_ 2334261106 S2A_ChgtimesatHightemp_50 "高温下累积充电时间";
CM_ SG_ 2334261106 S2A_DisChgtimesatHightemp_50 "高温下累积放电时间";
CM_ SG_ 2334261107 S2A_ChgtimesatHightemp_51 "高温下累积充电时间";
CM_ SG_ 2334261107 S2A_DisChgtimesatHightemp_51 "高温下累积放电时间";
CM_ SG_ 2334261108 S2A_ChgtimesatHightemp_52 "高温下累积充电时间";
CM_ SG_ 2334261108 S2A_DisChgtimesatHightemp_52 "高温下累积放电时间";
CM_ SG_ 2334261109 S2A_ChgtimesatHightemp_53 "高温下累积充电时间";
CM_ SG_ 2334261109 S2A_DisChgtimesatHightemp_53 "高温下累积放电时间";
CM_ SG_ 2334261110 S2A_ChgtimesatHightemp_54 "高温下累积充电时间";
CM_ SG_ 2334261110 S2A_DisChgtimesatHightemp_54 "高温下累积放电时间";
CM_ SG_ 2334261111 S2A_ChgtimesatHightemp_55 "高温下累积充电时间";
CM_ SG_ 2334261111 S2A_DisChgtimesatHightemp_55 "高温下累积放电时间";
CM_ SG_ 2334261112 S2A_ChgtimesatHightemp_56 "高温下累积充电时间";
CM_ SG_ 2334261112 S2A_DisChgtimesatHightemp_56 "高温下累积放电时间";
CM_ SG_ 2334261113 S2A_ChgtimesatHightemp_57 "高温下累积充电时间";
CM_ SG_ 2334261113 S2A_DisChgtimesatHightemp_57 "高温下累积放电时间";
CM_ SG_ 2334261114 S2A_ChgtimesatHightemp_58 "高温下累积充电时间";
CM_ SG_ 2334261114 S2A_DisChgtimesatHightemp_58 "高温下累积放电时间";
CM_ SG_ 2334261115 S2A_ChgtimesatHightemp_59 "高温下累积充电时间";
CM_ SG_ 2334261115 S2A_DisChgtimesatHightemp_59 "高温下累积放电时间";
CM_ SG_ 2334261116 S2A_ChgtimesatHightemp_60 "高温下累积充电时间";
CM_ SG_ 2334261116 S2A_DisChgtimesatHightemp_60 "高温下累积放电时间";
CM_ SG_ 2334261117 S2A_ChgtimesatHightemp_61 "高温下累积充电时间";
CM_ SG_ 2334261117 S2A_DisChgtimesatHightemp_61 "高温下累积放电时间";
CM_ SG_ 2334261118 S2A_ChgtimesatHightemp_62 "高温下累积充电时间";
CM_ SG_ 2334261118 S2A_DisChgtimesatHightemp_62 "高温下累积放电时间";
CM_ SG_ 2334261119 S2A_ChgtimesatHightemp_63 "高温下累积充电时间";
CM_ SG_ 2334261119 S2A_DisChgtimesatHightemp_63 "高温下累积放电时间";
CM_ SG_ 2332880529 M2P_STofSBMUAutoCoding_01 "SBMU地址自动编码状态";
CM_ SG_ 2332880530 M2P_STofSBMUAutoCoding_02 "SBMU地址自动编码状态";
CM_ SG_ 2332880531 M2P_STofSBMUAutoCoding_03 "SBMU地址自动编码状态";
CM_ SG_ 2332880532 M2P_STofSBMUAutoCoding_04 "SBMU地址自动编码状态";
CM_ SG_ 2332880533 M2P_STofSBMUAutoCoding_05 "SBMU地址自动编码状态";
CM_ SG_ 2332880534 M2P_STofSBMUAutoCoding_06 "SBMU地址自动编码状态";
CM_ SG_ 2332880535 M2P_STofSBMUAutoCoding_07 "SBMU地址自动编码状态";
CM_ SG_ 2332880536 M2P_STofSBMUAutoCoding_08 "SBMU地址自动编码状态";
CM_ SG_ 2332880537 M2P_STofSBMUAutoCoding_09 "SBMU地址自动编码状态";
CM_ SG_ 2332880538 M2P_STofSBMUAutoCoding_10 "SBMU地址自动编码状态";
CM_ SG_ 2332880539 M2P_STofSBMUAutoCoding_11 "SBMU地址自动编码状态";
CM_ SG_ 2332880540 M2P_STofSBMUAutoCoding_12 "SBMU地址自动编码状态";
CM_ SG_ 2332880541 M2P_STofSBMUAutoCoding_13 "SBMU地址自动编码状态";
CM_ SG_ 2332880542 M2P_STofSBMUAutoCoding_14 "SBMU地址自动编码状态";
CM_ SG_ 2332880543 M2P_STofSBMUAutoCoding_15 "SBMU地址自动编码状态";
CM_ SG_ 2332880544 M2P_STofSBMUAutoCoding_16 "SBMU地址自动编码状态";
CM_ SG_ 2332880545 M2P_STofSBMUAutoCoding_17 "SBMU地址自动编码状态";
CM_ SG_ 2332880546 M2P_STofSBMUAutoCoding_18 "SBMU地址自动编码状态";
CM_ SG_ 2332880547 M2P_STofSBMUAutoCoding_19 "SBMU地址自动编码状态";
CM_ SG_ 2332880548 M2P_STofSBMUAutoCoding_20 "SBMU地址自动编码状态";
CM_ SG_ 2332880549 M2P_STofSBMUAutoCoding_21 "SBMU地址自动编码状态";
CM_ SG_ 2332880550 M2P_STofSBMUAutoCoding_22 "SBMU地址自动编码状态";
CM_ SG_ 2332880551 M2P_STofSBMUAutoCoding_23 "SBMU地址自动编码状态";
CM_ SG_ 2332880552 M2P_STofSBMUAutoCoding_24 "SBMU地址自动编码状态";
CM_ SG_ 2332880553 M2P_STofSBMUAutoCoding_25 "SBMU地址自动编码状态";
CM_ SG_ 2332880554 M2P_STofSBMUAutoCoding_26 "SBMU地址自动编码状态";
CM_ SG_ 2332880555 M2P_STofSBMUAutoCoding_27 "SBMU地址自动编码状态";
CM_ SG_ 2332880556 M2P_STofSBMUAutoCoding_28 "SBMU地址自动编码状态";
CM_ SG_ 2332880557 M2P_STofSBMUAutoCoding_29 "SBMU地址自动编码状态";
CM_ SG_ 2332880558 M2P_STofSBMUAutoCoding_30 "SBMU地址自动编码状态";
CM_ SG_ 2332880559 M2P_STofSBMUAutoCoding_31 "SBMU地址自动编码状态";
CM_ SG_ 2165411822 P2A_CMD_StepChrSwitch "PC下发的Step-charge开启和关闭的指令";
CM_ SG_ 2484137617 E2M_CMD_BlackStart "ETH或PC下发的黑启动指令";
CM_ SG_ 2484137617 E2M_CMD_TMSPowerOff "EMS控制集中式TMS关机";
CM_ SG_ 2418077249 S2P_Lmt15_Over_UModule1_01 "电池模块充电电压一级报警值";
CM_ SG_ 2418077249 S2P_Lmt15_Over_RModule1_01 "电池模块充电电压一级恢复阈值";
CM_ SG_ 2418077249 S2P_Lmt15_Over_UModule2_01 "电池模块充电电压二级报警值";
CM_ SG_ 2418077249 S2P_Lmt15_Over_RModule2_01 "电池模块充电电压二级恢复阈值";
CM_ SG_ 2418077250 S2P_Lmt15_Over_UModule1_02 "电池模块充电电压一级报警值";
CM_ SG_ 2418077250 S2P_Lmt15_Over_RModule1_02 "电池模块充电电压一级恢复阈值";
CM_ SG_ 2418077250 S2P_Lmt15_Over_UModule2_02 "电池模块充电电压二级报警值";
CM_ SG_ 2418077250 S2P_Lmt15_Over_RModule2_02 "电池模块充电电压二级恢复阈值";
CM_ SG_ 2418077251 S2P_Lmt15_Over_UModule1_03 "电池模块充电电压一级报警值";
CM_ SG_ 2418077251 S2P_Lmt15_Over_RModule1_03 "电池模块充电电压一级恢复阈值";
CM_ SG_ 2418077251 S2P_Lmt15_Over_UModule2_03 "电池模块充电电压二级报警值";
CM_ SG_ 2418077251 S2P_Lmt15_Over_RModule2_03 "电池模块充电电压二级恢复阈值";
CM_ SG_ 2418077252 S2P_Lmt15_Over_UModule1_04 "电池模块充电电压一级报警值";
CM_ SG_ 2418077252 S2P_Lmt15_Over_RModule1_04 "电池模块充电电压一级恢复阈值";
CM_ SG_ 2418077252 S2P_Lmt15_Over_UModule2_04 "电池模块充电电压二级报警值";
CM_ SG_ 2418077252 S2P_Lmt15_Over_RModule2_04 "电池模块充电电压二级恢复阈值";
CM_ SG_ 2418077253 S2P_Lmt15_Over_UModule1_05 "电池模块充电电压一级报警值";
CM_ SG_ 2418077253 S2P_Lmt15_Over_RModule1_05 "电池模块充电电压一级恢复阈值";
CM_ SG_ 2418077253 S2P_Lmt15_Over_UModule2_05 "电池模块充电电压二级报警值";
CM_ SG_ 2418077253 S2P_Lmt15_Over_RModule2_05 "电池模块充电电压二级恢复阈值";
CM_ SG_ 2418077254 S2P_Lmt15_Over_UModule1_06 "电池模块充电电压一级报警值";
CM_ SG_ 2418077254 S2P_Lmt15_Over_RModule1_06 "电池模块充电电压一级恢复阈值";
CM_ SG_ 2418077254 S2P_Lmt15_Over_UModule2_06 "电池模块充电电压二级报警值";
CM_ SG_ 2418077254 S2P_Lmt15_Over_RModule2_06 "电池模块充电电压二级恢复阈值";
CM_ SG_ 2418077255 S2P_Lmt15_Over_UModule1_07 "电池模块充电电压一级报警值";
CM_ SG_ 2418077255 S2P_Lmt15_Over_RModule1_07 "电池模块充电电压一级恢复阈值";
CM_ SG_ 2418077255 S2P_Lmt15_Over_UModule2_07 "电池模块充电电压二级报警值";
CM_ SG_ 2418077255 S2P_Lmt15_Over_RModule2_07 "电池模块充电电压二级恢复阈值";
CM_ SG_ 2418077256 S2P_Lmt15_Over_UModule1_08 "电池模块充电电压一级报警值";
CM_ SG_ 2418077256 S2P_Lmt15_Over_RModule1_08 "电池模块充电电压一级恢复阈值";
CM_ SG_ 2418077256 S2P_Lmt15_Over_UModule2_08 "电池模块充电电压二级报警值";
CM_ SG_ 2418077256 S2P_Lmt15_Over_RModule2_08 "电池模块充电电压二级恢复阈值";
CM_ SG_ 2418077257 S2P_Lmt15_Over_UModule1_09 "电池模块充电电压一级报警值";
CM_ SG_ 2418077257 S2P_Lmt15_Over_RModule1_09 "电池模块充电电压一级恢复阈值";
CM_ SG_ 2418077257 S2P_Lmt15_Over_UModule2_09 "电池模块充电电压二级报警值";
CM_ SG_ 2418077257 S2P_Lmt15_Over_RModule2_09 "电池模块充电电压二级恢复阈值";
CM_ SG_ 2418077258 S2P_Lmt15_Over_UModule1_10 "电池模块充电电压一级报警值";
CM_ SG_ 2418077258 S2P_Lmt15_Over_RModule1_10 "电池模块充电电压一级恢复阈值";
CM_ SG_ 2418077258 S2P_Lmt15_Over_UModule2_10 "电池模块充电电压二级报警值";
CM_ SG_ 2418077258 S2P_Lmt15_Over_RModule2_10 "电池模块充电电压二级恢复阈值";
CM_ SG_ 2418077259 S2P_Lmt15_Over_UModule1_11 "电池模块充电电压一级报警值";
CM_ SG_ 2418077259 S2P_Lmt15_Over_RModule1_11 "电池模块充电电压一级恢复阈值";
CM_ SG_ 2418077259 S2P_Lmt15_Over_UModule2_11 "电池模块充电电压二级报警值";
CM_ SG_ 2418077259 S2P_Lmt15_Over_RModule2_11 "电池模块充电电压二级恢复阈值";
CM_ SG_ 2418077260 S2P_Lmt15_Over_UModule1_12 "电池模块充电电压一级报警值";
CM_ SG_ 2418077260 S2P_Lmt15_Over_RModule1_12 "电池模块充电电压一级恢复阈值";
CM_ SG_ 2418077260 S2P_Lmt15_Over_UModule2_12 "电池模块充电电压二级报警值";
CM_ SG_ 2418077260 S2P_Lmt15_Over_RModule2_12 "电池模块充电电压二级恢复阈值";
CM_ SG_ 2418077261 S2P_Lmt15_Over_UModule1_13 "电池模块充电电压一级报警值";
CM_ SG_ 2418077261 S2P_Lmt15_Over_RModule1_13 "电池模块充电电压一级恢复阈值";
CM_ SG_ 2418077261 S2P_Lmt15_Over_UModule2_13 "电池模块充电电压二级报警值";
CM_ SG_ 2418077261 S2P_Lmt15_Over_RModule2_13 "电池模块充电电压二级恢复阈值";
CM_ SG_ 2418077262 S2P_Lmt15_Over_UModule1_14 "电池模块充电电压一级报警值";
CM_ SG_ 2418077262 S2P_Lmt15_Over_RModule1_14 "电池模块充电电压一级恢复阈值";
CM_ SG_ 2418077262 S2P_Lmt15_Over_UModule2_14 "电池模块充电电压二级报警值";
CM_ SG_ 2418077262 S2P_Lmt15_Over_RModule2_14 "电池模块充电电压二级恢复阈值";
CM_ SG_ 2418077263 S2P_Lmt15_Over_UModule1_15 "电池模块充电电压一级报警值";
CM_ SG_ 2418077263 S2P_Lmt15_Over_RModule1_15 "电池模块充电电压一级恢复阈值";
CM_ SG_ 2418077263 S2P_Lmt15_Over_UModule2_15 "电池模块充电电压二级报警值";
CM_ SG_ 2418077263 S2P_Lmt15_Over_RModule2_15 "电池模块充电电压二级恢复阈值";
CM_ SG_ 2418077264 S2P_Lmt15_Over_UModule1_16 "电池模块充电电压一级报警值";
CM_ SG_ 2418077264 S2P_Lmt15_Over_RModule1_16 "电池模块充电电压一级恢复阈值";
CM_ SG_ 2418077264 S2P_Lmt15_Over_UModule2_16 "电池模块充电电压二级报警值";
CM_ SG_ 2418077264 S2P_Lmt15_Over_RModule2_16 "电池模块充电电压二级恢复阈值";
CM_ SG_ 2418077265 S2P_Lmt15_Over_UModule1_17 "电池模块充电电压一级报警值";
CM_ SG_ 2418077265 S2P_Lmt15_Over_RModule1_17 "电池模块充电电压一级恢复阈值";
CM_ SG_ 2418077265 S2P_Lmt15_Over_UModule2_17 "电池模块充电电压二级报警值";
CM_ SG_ 2418077265 S2P_Lmt15_Over_RModule2_17 "电池模块充电电压二级恢复阈值";
CM_ SG_ 2418077266 S2P_Lmt15_Over_UModule1_18 "电池模块充电电压一级报警值";
CM_ SG_ 2418077266 S2P_Lmt15_Over_RModule1_18 "电池模块充电电压一级恢复阈值";
CM_ SG_ 2418077266 S2P_Lmt15_Over_UModule2_18 "电池模块充电电压二级报警值";
CM_ SG_ 2418077266 S2P_Lmt15_Over_RModule2_18 "电池模块充电电压二级恢复阈值";
CM_ SG_ 2418077267 S2P_Lmt15_Over_UModule1_19 "电池模块充电电压一级报警值";
CM_ SG_ 2418077267 S2P_Lmt15_Over_RModule1_19 "电池模块充电电压一级恢复阈值";
CM_ SG_ 2418077267 S2P_Lmt15_Over_UModule2_19 "电池模块充电电压二级报警值";
CM_ SG_ 2418077267 S2P_Lmt15_Over_RModule2_19 "电池模块充电电压二级恢复阈值";
CM_ SG_ 2418077268 S2P_Lmt15_Over_UModule1_20 "电池模块充电电压一级报警值";
CM_ SG_ 2418077268 S2P_Lmt15_Over_RModule1_20 "电池模块充电电压一级恢复阈值";
CM_ SG_ 2418077268 S2P_Lmt15_Over_UModule2_20 "电池模块充电电压二级报警值";
CM_ SG_ 2418077268 S2P_Lmt15_Over_RModule2_20 "电池模块充电电压二级恢复阈值";
CM_ SG_ 2418077269 S2P_Lmt15_Over_UModule1_21 "电池模块充电电压一级报警值";
CM_ SG_ 2418077269 S2P_Lmt15_Over_RModule1_21 "电池模块充电电压一级恢复阈值";
CM_ SG_ 2418077269 S2P_Lmt15_Over_UModule2_21 "电池模块充电电压二级报警值";
CM_ SG_ 2418077269 S2P_Lmt15_Over_RModule2_21 "电池模块充电电压二级恢复阈值";
CM_ SG_ 2418077270 S2P_Lmt15_Over_UModule1_22 "电池模块充电电压一级报警值";
CM_ SG_ 2418077270 S2P_Lmt15_Over_RModule1_22 "电池模块充电电压一级恢复阈值";
CM_ SG_ 2418077270 S2P_Lmt15_Over_UModule2_22 "电池模块充电电压二级报警值";
CM_ SG_ 2418077270 S2P_Lmt15_Over_RModule2_22 "电池模块充电电压二级恢复阈值";
CM_ SG_ 2418077271 S2P_Lmt15_Over_UModule1_23 "电池模块充电电压一级报警值";
CM_ SG_ 2418077271 S2P_Lmt15_Over_RModule1_23 "电池模块充电电压一级恢复阈值";
CM_ SG_ 2418077271 S2P_Lmt15_Over_UModule2_23 "电池模块充电电压二级报警值";
CM_ SG_ 2418077271 S2P_Lmt15_Over_RModule2_23 "电池模块充电电压二级恢复阈值";
CM_ SG_ 2418077272 S2P_Lmt15_Over_UModule1_24 "电池模块充电电压一级报警值";
CM_ SG_ 2418077272 S2P_Lmt15_Over_RModule1_24 "电池模块充电电压一级恢复阈值";
CM_ SG_ 2418077272 S2P_Lmt15_Over_UModule2_24 "电池模块充电电压二级报警值";
CM_ SG_ 2418077272 S2P_Lmt15_Over_RModule2_24 "电池模块充电电压二级恢复阈值";
CM_ SG_ 2418077273 S2P_Lmt15_Over_UModule1_25 "电池模块充电电压一级报警值";
CM_ SG_ 2418077273 S2P_Lmt15_Over_RModule1_25 "电池模块充电电压一级恢复阈值";
CM_ SG_ 2418077273 S2P_Lmt15_Over_UModule2_25 "电池模块充电电压二级报警值";
CM_ SG_ 2418077273 S2P_Lmt15_Over_RModule2_25 "电池模块充电电压二级恢复阈值";
CM_ SG_ 2418077274 S2P_Lmt15_Over_UModule1_26 "电池模块充电电压一级报警值";
CM_ SG_ 2418077274 S2P_Lmt15_Over_RModule1_26 "电池模块充电电压一级恢复阈值";
CM_ SG_ 2418077274 S2P_Lmt15_Over_UModule2_26 "电池模块充电电压二级报警值";
CM_ SG_ 2418077274 S2P_Lmt15_Over_RModule2_26 "电池模块充电电压二级恢复阈值";
CM_ SG_ 2418077275 S2P_Lmt15_Over_UModule1_27 "电池模块充电电压一级报警值";
CM_ SG_ 2418077275 S2P_Lmt15_Over_RModule1_27 "电池模块充电电压一级恢复阈值";
CM_ SG_ 2418077275 S2P_Lmt15_Over_UModule2_27 "电池模块充电电压二级报警值";
CM_ SG_ 2418077275 S2P_Lmt15_Over_RModule2_27 "电池模块充电电压二级恢复阈值";
CM_ SG_ 2418077276 S2P_Lmt15_Over_UModule1_28 "电池模块充电电压一级报警值";
CM_ SG_ 2418077276 S2P_Lmt15_Over_RModule1_28 "电池模块充电电压一级恢复阈值";
CM_ SG_ 2418077276 S2P_Lmt15_Over_UModule2_28 "电池模块充电电压二级报警值";
CM_ SG_ 2418077276 S2P_Lmt15_Over_RModule2_28 "电池模块充电电压二级恢复阈值";
CM_ SG_ 2418077277 S2P_Lmt15_Over_UModule1_29 "电池模块充电电压一级报警值";
CM_ SG_ 2418077277 S2P_Lmt15_Over_RModule1_29 "电池模块充电电压一级恢复阈值";
CM_ SG_ 2418077277 S2P_Lmt15_Over_UModule2_29 "电池模块充电电压二级报警值";
CM_ SG_ 2418077277 S2P_Lmt15_Over_RModule2_29 "电池模块充电电压二级恢复阈值";
CM_ SG_ 2418077278 S2P_Lmt15_Over_UModule1_30 "电池模块充电电压一级报警值";
CM_ SG_ 2418077278 S2P_Lmt15_Over_RModule1_30 "电池模块充电电压一级恢复阈值";
CM_ SG_ 2418077278 S2P_Lmt15_Over_UModule2_30 "电池模块充电电压二级报警值";
CM_ SG_ 2418077278 S2P_Lmt15_Over_RModule2_30 "电池模块充电电压二级恢复阈值";
CM_ SG_ 2418077279 S2P_Lmt15_Over_UModule1_31 "电池模块充电电压一级报警值";
CM_ SG_ 2418077279 S2P_Lmt15_Over_RModule1_31 "电池模块充电电压一级恢复阈值";
CM_ SG_ 2418077279 S2P_Lmt15_Over_UModule2_31 "电池模块充电电压二级报警值";
CM_ SG_ 2418077279 S2P_Lmt15_Over_RModule2_31 "电池模块充电电压二级恢复阈值";
CM_ SG_ 2418077280 S2P_Lmt15_Over_UModule1_32 "电池模块充电电压一级报警值";
CM_ SG_ 2418077280 S2P_Lmt15_Over_RModule1_32 "电池模块充电电压一级恢复阈值";
CM_ SG_ 2418077280 S2P_Lmt15_Over_UModule2_32 "电池模块充电电压二级报警值";
CM_ SG_ 2418077280 S2P_Lmt15_Over_RModule2_32 "电池模块充电电压二级恢复阈值";
CM_ SG_ 2418077281 S2P_Lmt15_Over_UModule1_33 "电池模块充电电压一级报警值";
CM_ SG_ 2418077281 S2P_Lmt15_Over_RModule1_33 "电池模块充电电压一级恢复阈值";
CM_ SG_ 2418077281 S2P_Lmt15_Over_UModule2_33 "电池模块充电电压二级报警值";
CM_ SG_ 2418077281 S2P_Lmt15_Over_RModule2_33 "电池模块充电电压二级恢复阈值";
CM_ SG_ 2418077282 S2P_Lmt15_Over_UModule1_34 "电池模块充电电压一级报警值";
CM_ SG_ 2418077282 S2P_Lmt15_Over_RModule1_34 "电池模块充电电压一级恢复阈值";
CM_ SG_ 2418077282 S2P_Lmt15_Over_UModule2_34 "电池模块充电电压二级报警值";
CM_ SG_ 2418077282 S2P_Lmt15_Over_RModule2_34 "电池模块充电电压二级恢复阈值";
CM_ SG_ 2418077283 S2P_Lmt15_Over_UModule1_35 "电池模块充电电压一级报警值";
CM_ SG_ 2418077283 S2P_Lmt15_Over_RModule1_35 "电池模块充电电压一级恢复阈值";
CM_ SG_ 2418077283 S2P_Lmt15_Over_UModule2_35 "电池模块充电电压二级报警值";
CM_ SG_ 2418077283 S2P_Lmt15_Over_RModule2_35 "电池模块充电电压二级恢复阈值";
CM_ SG_ 2418077284 S2P_Lmt15_Over_UModule1_36 "电池模块充电电压一级报警值";
CM_ SG_ 2418077284 S2P_Lmt15_Over_RModule1_36 "电池模块充电电压一级恢复阈值";
CM_ SG_ 2418077284 S2P_Lmt15_Over_UModule2_36 "电池模块充电电压二级报警值";
CM_ SG_ 2418077284 S2P_Lmt15_Over_RModule2_36 "电池模块充电电压二级恢复阈值";
CM_ SG_ 2418077285 S2P_Lmt15_Over_UModule1_37 "电池模块充电电压一级报警值";
CM_ SG_ 2418077285 S2P_Lmt15_Over_RModule1_37 "电池模块充电电压一级恢复阈值";
CM_ SG_ 2418077285 S2P_Lmt15_Over_UModule2_37 "电池模块充电电压二级报警值";
CM_ SG_ 2418077285 S2P_Lmt15_Over_RModule2_37 "电池模块充电电压二级恢复阈值";
CM_ SG_ 2418077286 S2P_Lmt15_Over_UModule1_38 "电池模块充电电压一级报警值";
CM_ SG_ 2418077286 S2P_Lmt15_Over_RModule1_38 "电池模块充电电压一级恢复阈值";
CM_ SG_ 2418077286 S2P_Lmt15_Over_UModule2_38 "电池模块充电电压二级报警值";
CM_ SG_ 2418077286 S2P_Lmt15_Over_RModule2_38 "电池模块充电电压二级恢复阈值";
CM_ SG_ 2418077287 S2P_Lmt15_Over_UModule1_39 "电池模块充电电压一级报警值";
CM_ SG_ 2418077287 S2P_Lmt15_Over_RModule1_39 "电池模块充电电压一级恢复阈值";
CM_ SG_ 2418077287 S2P_Lmt15_Over_UModule2_39 "电池模块充电电压二级报警值";
CM_ SG_ 2418077287 S2P_Lmt15_Over_RModule2_39 "电池模块充电电压二级恢复阈值";
CM_ SG_ 2418077288 S2P_Lmt15_Over_UModule1_40 "电池模块充电电压一级报警值";
CM_ SG_ 2418077288 S2P_Lmt15_Over_RModule1_40 "电池模块充电电压一级恢复阈值";
CM_ SG_ 2418077288 S2P_Lmt15_Over_UModule2_40 "电池模块充电电压二级报警值";
CM_ SG_ 2418077288 S2P_Lmt15_Over_RModule2_40 "电池模块充电电压二级恢复阈值";
CM_ SG_ 2418077289 S2P_Lmt15_Over_UModule1_41 "电池模块充电电压一级报警值";
CM_ SG_ 2418077289 S2P_Lmt15_Over_RModule1_41 "电池模块充电电压一级恢复阈值";
CM_ SG_ 2418077289 S2P_Lmt15_Over_UModule2_41 "电池模块充电电压二级报警值";
CM_ SG_ 2418077289 S2P_Lmt15_Over_RModule2_41 "电池模块充电电压二级恢复阈值";
CM_ SG_ 2418077290 S2P_Lmt15_Over_UModule1_42 "电池模块充电电压一级报警值";
CM_ SG_ 2418077290 S2P_Lmt15_Over_RModule1_42 "电池模块充电电压一级恢复阈值";
CM_ SG_ 2418077290 S2P_Lmt15_Over_UModule2_42 "电池模块充电电压二级报警值";
CM_ SG_ 2418077290 S2P_Lmt15_Over_RModule2_42 "电池模块充电电压二级恢复阈值";
CM_ SG_ 2418077291 S2P_Lmt15_Over_UModule1_43 "电池模块充电电压一级报警值";
CM_ SG_ 2418077291 S2P_Lmt15_Over_RModule1_43 "电池模块充电电压一级恢复阈值";
CM_ SG_ 2418077291 S2P_Lmt15_Over_UModule2_43 "电池模块充电电压二级报警值";
CM_ SG_ 2418077291 S2P_Lmt15_Over_RModule2_43 "电池模块充电电压二级恢复阈值";
CM_ SG_ 2418077292 S2P_Lmt15_Over_UModule1_44 "电池模块充电电压一级报警值";
CM_ SG_ 2418077292 S2P_Lmt15_Over_RModule1_44 "电池模块充电电压一级恢复阈值";
CM_ SG_ 2418077292 S2P_Lmt15_Over_UModule2_44 "电池模块充电电压二级报警值";
CM_ SG_ 2418077292 S2P_Lmt15_Over_RModule2_44 "电池模块充电电压二级恢复阈值";
CM_ SG_ 2418077293 S2P_Lmt15_Over_UModule1_45 "电池模块充电电压一级报警值";
CM_ SG_ 2418077293 S2P_Lmt15_Over_RModule1_45 "电池模块充电电压一级恢复阈值";
CM_ SG_ 2418077293 S2P_Lmt15_Over_UModule2_45 "电池模块充电电压二级报警值";
CM_ SG_ 2418077293 S2P_Lmt15_Over_RModule2_45 "电池模块充电电压二级恢复阈值";
CM_ SG_ 2418077294 S2P_Lmt15_Over_UModule1_46 "电池模块充电电压一级报警值";
CM_ SG_ 2418077294 S2P_Lmt15_Over_RModule1_46 "电池模块充电电压一级恢复阈值";
CM_ SG_ 2418077294 S2P_Lmt15_Over_UModule2_46 "电池模块充电电压二级报警值";
CM_ SG_ 2418077294 S2P_Lmt15_Over_RModule2_46 "电池模块充电电压二级恢复阈值";
CM_ SG_ 2418077295 S2P_Lmt15_Over_UModule1_47 "电池模块充电电压一级报警值";
CM_ SG_ 2418077295 S2P_Lmt15_Over_RModule1_47 "电池模块充电电压一级恢复阈值";
CM_ SG_ 2418077295 S2P_Lmt15_Over_UModule2_47 "电池模块充电电压二级报警值";
CM_ SG_ 2418077295 S2P_Lmt15_Over_RModule2_47 "电池模块充电电压二级恢复阈值";
CM_ SG_ 2418077296 S2P_Lmt15_Over_UModule1_48 "电池模块充电电压一级报警值";
CM_ SG_ 2418077296 S2P_Lmt15_Over_RModule1_48 "电池模块充电电压一级恢复阈值";
CM_ SG_ 2418077296 S2P_Lmt15_Over_UModule2_48 "电池模块充电电压二级报警值";
CM_ SG_ 2418077296 S2P_Lmt15_Over_RModule2_48 "电池模块充电电压二级恢复阈值";
CM_ SG_ 2418077297 S2P_Lmt15_Over_UModule1_49 "电池模块充电电压一级报警值";
CM_ SG_ 2418077297 S2P_Lmt15_Over_RModule1_49 "电池模块充电电压一级恢复阈值";
CM_ SG_ 2418077297 S2P_Lmt15_Over_UModule2_49 "电池模块充电电压二级报警值";
CM_ SG_ 2418077297 S2P_Lmt15_Over_RModule2_49 "电池模块充电电压二级恢复阈值";
CM_ SG_ 2418077298 S2P_Lmt15_Over_UModule1_50 "电池模块充电电压一级报警值";
CM_ SG_ 2418077298 S2P_Lmt15_Over_RModule1_50 "电池模块充电电压一级恢复阈值";
CM_ SG_ 2418077298 S2P_Lmt15_Over_UModule2_50 "电池模块充电电压二级报警值";
CM_ SG_ 2418077298 S2P_Lmt15_Over_RModule2_50 "电池模块充电电压二级恢复阈值";
CM_ SG_ 2418077299 S2P_Lmt15_Over_UModule1_51 "电池模块充电电压一级报警值";
CM_ SG_ 2418077299 S2P_Lmt15_Over_RModule1_51 "电池模块充电电压一级恢复阈值";
CM_ SG_ 2418077299 S2P_Lmt15_Over_UModule2_51 "电池模块充电电压二级报警值";
CM_ SG_ 2418077299 S2P_Lmt15_Over_RModule2_51 "电池模块充电电压二级恢复阈值";
CM_ SG_ 2418077300 S2P_Lmt15_Over_UModule1_52 "电池模块充电电压一级报警值";
CM_ SG_ 2418077300 S2P_Lmt15_Over_RModule1_52 "电池模块充电电压一级恢复阈值";
CM_ SG_ 2418077300 S2P_Lmt15_Over_UModule2_52 "电池模块充电电压二级报警值";
CM_ SG_ 2418077300 S2P_Lmt15_Over_RModule2_52 "电池模块充电电压二级恢复阈值";
CM_ SG_ 2418077301 S2P_Lmt15_Over_UModule1_53 "电池模块充电电压一级报警值";
CM_ SG_ 2418077301 S2P_Lmt15_Over_RModule1_53 "电池模块充电电压一级恢复阈值";
CM_ SG_ 2418077301 S2P_Lmt15_Over_UModule2_53 "电池模块充电电压二级报警值";
CM_ SG_ 2418077301 S2P_Lmt15_Over_RModule2_53 "电池模块充电电压二级恢复阈值";
CM_ SG_ 2418077302 S2P_Lmt15_Over_UModule1_54 "电池模块充电电压一级报警值";
CM_ SG_ 2418077302 S2P_Lmt15_Over_RModule1_54 "电池模块充电电压一级恢复阈值";
CM_ SG_ 2418077302 S2P_Lmt15_Over_UModule2_54 "电池模块充电电压二级报警值";
CM_ SG_ 2418077302 S2P_Lmt15_Over_RModule2_54 "电池模块充电电压二级恢复阈值";
CM_ SG_ 2418077303 S2P_Lmt15_Over_UModule1_55 "电池模块充电电压一级报警值";
CM_ SG_ 2418077303 S2P_Lmt15_Over_RModule1_55 "电池模块充电电压一级恢复阈值";
CM_ SG_ 2418077303 S2P_Lmt15_Over_UModule2_55 "电池模块充电电压二级报警值";
CM_ SG_ 2418077303 S2P_Lmt15_Over_RModule2_55 "电池模块充电电压二级恢复阈值";
CM_ SG_ 2418077304 S2P_Lmt15_Over_UModule1_56 "电池模块充电电压一级报警值";
CM_ SG_ 2418077304 S2P_Lmt15_Over_RModule1_56 "电池模块充电电压一级恢复阈值";
CM_ SG_ 2418077304 S2P_Lmt15_Over_UModule2_56 "电池模块充电电压二级报警值";
CM_ SG_ 2418077304 S2P_Lmt15_Over_RModule2_56 "电池模块充电电压二级恢复阈值";
CM_ SG_ 2418077305 S2P_Lmt15_Over_UModule1_57 "电池模块充电电压一级报警值";
CM_ SG_ 2418077305 S2P_Lmt15_Over_RModule1_57 "电池模块充电电压一级恢复阈值";
CM_ SG_ 2418077305 S2P_Lmt15_Over_UModule2_57 "电池模块充电电压二级报警值";
CM_ SG_ 2418077305 S2P_Lmt15_Over_RModule2_57 "电池模块充电电压二级恢复阈值";
CM_ SG_ 2418077306 S2P_Lmt15_Over_UModule1_58 "电池模块充电电压一级报警值";
CM_ SG_ 2418077306 S2P_Lmt15_Over_RModule1_58 "电池模块充电电压一级恢复阈值";
CM_ SG_ 2418077306 S2P_Lmt15_Over_UModule2_58 "电池模块充电电压二级报警值";
CM_ SG_ 2418077306 S2P_Lmt15_Over_RModule2_58 "电池模块充电电压二级恢复阈值";
CM_ SG_ 2418077307 S2P_Lmt15_Over_UModule1_59 "电池模块充电电压一级报警值";
CM_ SG_ 2418077307 S2P_Lmt15_Over_RModule1_59 "电池模块充电电压一级恢复阈值";
CM_ SG_ 2418077307 S2P_Lmt15_Over_UModule2_59 "电池模块充电电压二级报警值";
CM_ SG_ 2418077307 S2P_Lmt15_Over_RModule2_59 "电池模块充电电压二级恢复阈值";
VAL_ 2332880529 M2P_STofSBMUAutoCoding_01 0 "Initial" 1 "Successful" 2 "Failed" 3 "In Coding process" 4 "No Coding required" ;
VAL_ 2332880530 M2P_STofSBMUAutoCoding_02 0 "Initial" 1 "Successful" 2 "Failed" 3 "In Coding process" 4 "No Coding required" ;
VAL_ 2332880531 M2P_STofSBMUAutoCoding_03 0 "Initial" 1 "Successful" 2 "Failed" 3 "In Coding process" 4 "No Coding required" ;
VAL_ 2332880532 M2P_STofSBMUAutoCoding_04 0 "Initial" 1 "Successful" 2 "Failed" 3 "In Coding process" 4 "No Coding required" ;
VAL_ 2332880533 M2P_STofSBMUAutoCoding_05 0 "Initial" 1 "Successful" 2 "Failed" 3 "In Coding process" 4 "No Coding required" ;
VAL_ 2332880534 M2P_STofSBMUAutoCoding_06 0 "Initial" 1 "Successful" 2 "Failed" 3 "In Coding process" 4 "No Coding required" ;
VAL_ 2332880535 M2P_STofSBMUAutoCoding_07 0 "Initial" 1 "Successful" 2 "Failed" 3 "In Coding process" 4 "No Coding required" ;
VAL_ 2332880536 M2P_STofSBMUAutoCoding_08 0 "Initial" 1 "Successful" 2 "Failed" 3 "In Coding process" 4 "No Coding required" ;
VAL_ 2332880537 M2P_STofSBMUAutoCoding_09 0 "Initial" 1 "Successful" 2 "Failed" 3 "In Coding process" 4 "No Coding required" ;
VAL_ 2332880538 M2P_STofSBMUAutoCoding_10 0 "Initial" 1 "Successful" 2 "Failed" 3 "In Coding process" 4 "No Coding required" ;
VAL_ 2332880539 M2P_STofSBMUAutoCoding_11 0 "Initial" 1 "Successful" 2 "Failed" 3 "In Coding process" 4 "No Coding required" ;
VAL_ 2332880540 M2P_STofSBMUAutoCoding_12 0 "Initial" 1 "Successful" 2 "Failed" 3 "In Coding process" 4 "No Coding required" ;
VAL_ 2332880541 M2P_STofSBMUAutoCoding_13 0 "Initial" 1 "Successful" 2 "Failed" 3 "In Coding process" 4 "No Coding required" ;
VAL_ 2332880542 M2P_STofSBMUAutoCoding_14 0 "Initial" 1 "Successful" 2 "Failed" 3 "In Coding process" 4 "No Coding required" ;
VAL_ 2332880543 M2P_STofSBMUAutoCoding_15 0 "Initial" 1 "Successful" 2 "Failed" 3 "In Coding process" 4 "No Coding required" ;
VAL_ 2332880544 M2P_STofSBMUAutoCoding_16 0 "Initial" 1 "Successful" 2 "Failed" 3 "In Coding process" 4 "No Coding required" ;
VAL_ 2332880545 M2P_STofSBMUAutoCoding_17 0 "Initial" 1 "Successful" 2 "Failed" 3 "In Coding process" 4 "No Coding required" ;
VAL_ 2332880546 M2P_STofSBMUAutoCoding_18 0 "Initial" 1 "Successful" 2 "Failed" 3 "In Coding process" 4 "No Coding required" ;
VAL_ 2332880547 M2P_STofSBMUAutoCoding_19 0 "Initial" 1 "Successful" 2 "Failed" 3 "In Coding process" 4 "No Coding required" ;
VAL_ 2332880548 M2P_STofSBMUAutoCoding_20 0 "Initial" 1 "Successful" 2 "Failed" 3 "In Coding process" 4 "No Coding required" ;
VAL_ 2332880549 M2P_STofSBMUAutoCoding_21 0 "Initial" 1 "Successful" 2 "Failed" 3 "In Coding process" 4 "No Coding required" ;
VAL_ 2332880550 M2P_STofSBMUAutoCoding_22 0 "Initial" 1 "Successful" 2 "Failed" 3 "In Coding process" 4 "No Coding required" ;
VAL_ 2332880551 M2P_STofSBMUAutoCoding_23 0 "Initial" 1 "Successful" 2 "Failed" 3 "In Coding process" 4 "No Coding required" ;
VAL_ 2332880552 M2P_STofSBMUAutoCoding_24 0 "Initial" 1 "Successful" 2 "Failed" 3 "In Coding process" 4 "No Coding required" ;
VAL_ 2332880553 M2P_STofSBMUAutoCoding_25 0 "Initial" 1 "Successful" 2 "Failed" 3 "In Coding process" 4 "No Coding required" ;
VAL_ 2332880554 M2P_STofSBMUAutoCoding_26 0 "Initial" 1 "Successful" 2 "Failed" 3 "In Coding process" 4 "No Coding required" ;
VAL_ 2332880555 M2P_STofSBMUAutoCoding_27 0 "Initial" 1 "Successful" 2 "Failed" 3 "In Coding process" 4 "No Coding required" ;
VAL_ 2332880556 M2P_STofSBMUAutoCoding_28 0 "Initial" 1 "Successful" 2 "Failed" 3 "In Coding process" 4 "No Coding required" ;
VAL_ 2332880557 M2P_STofSBMUAutoCoding_29 0 "Initial" 1 "Successful" 2 "Failed" 3 "In Coding process" 4 "No Coding required" ;
VAL_ 2332880558 M2P_STofSBMUAutoCoding_30 0 "Initial" 1 "Successful" 2 "Failed" 3 "In Coding process" 4 "No Coding required" ;
VAL_ 2332880559 M2P_STofSBMUAutoCoding_31 0 "Initial" 1 "Successful" 2 "Failed" 3 "In Coding process" 4 "No Coding required" ;
VAL_ 2165411822 P2A_CMD_StepChrSwitch 0 "初始化" 1 "关闭step_charge" 2 "开启step_charge" ;
VAL_ 2484137617 E2M_CMD_BlackStart 0 "narmal" 3 "黑启动状态" ;
VAL_ 2484137617 E2M_CMD_TMSPowerOff 0 "无效" 1 "EMS控制集中式TMS关机信号置位" ;
VERSION ""

NS_ :

BS_:

BU_: MBMU PC SBMU IMM ETH DCDC LEMS

BO_ 2418077308 S2P_Lmt15__60: 8 SBMU
 SG_ S2P_Lmt15_Over_UModule1_60 : 0|16@1+ (0.1,0) [0|6553.5] "V"  PC
 SG_ S2P_Lmt15_Over_RModule1_60 : 16|16@1+ (0.1,0) [0|6553.5] "V"  PC
 SG_ S2P_Lmt15_Over_UModule2_60 : 32|16@1+ (0.1,0) [0|6553.5] "V"  PC
 SG_ S2P_Lmt15_Over_RModule2_60 : 48|16@1+ (0.1,0) [0|6553.5] "V"  PC

BO_ 2418077309 S2P_Lmt15__61: 8 SBMU
 SG_ S2P_Lmt15_Over_UModule1_61 : 0|16@1+ (0.1,0) [0|6553.5] "V"  PC
 SG_ S2P_Lmt15_Over_RModule1_61 : 16|16@1+ (0.1,0) [0|6553.5] "V"  PC
 SG_ S2P_Lmt15_Over_UModule2_61 : 32|16@1+ (0.1,0) [0|6553.5] "V"  PC
 SG_ S2P_Lmt15_Over_RModule2_61 : 48|16@1+ (0.1,0) [0|6553.5] "V"  PC

BO_ 2418077310 S2P_Lmt15__62: 8 SBMU
 SG_ S2P_Lmt15_Over_UModule1_62 : 0|16@1+ (0.1,0) [0|6553.5] "V"  PC
 SG_ S2P_Lmt15_Over_RModule1_62 : 16|16@1+ (0.1,0) [0|6553.5] "V"  PC
 SG_ S2P_Lmt15_Over_UModule2_62 : 32|16@1+ (0.1,0) [0|6553.5] "V"  PC
 SG_ S2P_Lmt15_Over_RModule2_62 : 48|16@1+ (0.1,0) [0|6553.5] "V"  PC

BO_ 2418077311 S2P_Lmt15__63: 8 SBMU
 SG_ S2P_Lmt15_Over_UModule1_63 : 0|16@1+ (0.1,0) [0|6553.5] "V"  PC
 SG_ S2P_Lmt15_Over_RModule1_63 : 16|16@1+ (0.1,0) [0|6553.5] "V"  PC
 SG_ S2P_Lmt15_Over_UModule2_63 : 32|16@1+ (0.1,0) [0|6553.5] "V"  PC
 SG_ S2P_Lmt15_Over_RModule2_63 : 48|16@1+ (0.1,0) [0|6553.5] "V"  PC

BO_ 2418142785 S2P_Lmt16__01: 8 SBMU
 SG_ S2P_Lmt16_Under_UModule1_01 : 0|16@1+ (0.1,0) [0|6553.5] "V"  PC
 SG_ S2P_Lmt16_Under_RModule1_01 : 16|16@1+ (0.1,0) [0|6553.5] "V"  PC
 SG_ S2P_Lmt16_Under_UModule2_01 : 32|16@1+ (0.1,0) [0|6553.5] "V"  PC
 SG_ S2P_Lmt16_Under_RModule2_01 : 48|16@1+ (0.1,0) [0|6553.5] "V"  PC

BO_ 2418142786 S2P_Lmt16__02: 8 SBMU
 SG_ S2P_Lmt16_Under_UModule1_02 : 0|16@1+ (0.1,0) [0|6553.5] "V"  PC
 SG_ S2P_Lmt16_Under_RModule1_02 : 16|16@1+ (0.1,0) [0|6553.5] "V"  PC
 SG_ S2P_Lmt16_Under_UModule2_02 : 32|16@1+ (0.1,0) [0|6553.5] "V"  PC
 SG_ S2P_Lmt16_Under_RModule2_02 : 48|16@1+ (0.1,0) [0|6553.5] "V"  PC

BO_ 2418142787 S2P_Lmt16__03: 8 SBMU
 SG_ S2P_Lmt16_Under_UModule1_03 : 0|16@1+ (0.1,0) [0|6553.5] "V"  PC
 SG_ S2P_Lmt16_Under_RModule1_03 : 16|16@1+ (0.1,0) [0|6553.5] "V"  PC
 SG_ S2P_Lmt16_Under_UModule2_03 : 32|16@1+ (0.1,0) [0|6553.5] "V"  PC
 SG_ S2P_Lmt16_Under_RModule2_03 : 48|16@1+ (0.1,0) [0|6553.5] "V"  PC

BO_ 2418142788 S2P_Lmt16__04: 8 SBMU
 SG_ S2P_Lmt16_Under_UModule1_04 : 0|16@1+ (0.1,0) [0|6553.5] "V"  PC
 SG_ S2P_Lmt16_Under_RModule1_04 : 16|16@1+ (0.1,0) [0|6553.5] "V"  PC
 SG_ S2P_Lmt16_Under_UModule2_04 : 32|16@1+ (0.1,0) [0|6553.5] "V"  PC
 SG_ S2P_Lmt16_Under_RModule2_04 : 48|16@1+ (0.1,0) [0|6553.5] "V"  PC

BO_ 2418142789 S2P_Lmt16__05: 8 SBMU
 SG_ S2P_Lmt16_Under_UModule1_05 : 0|16@1+ (0.1,0) [0|6553.5] "V"  PC
 SG_ S2P_Lmt16_Under_RModule1_05 : 16|16@1+ (0.1,0) [0|6553.5] "V"  PC
 SG_ S2P_Lmt16_Under_UModule2_05 : 32|16@1+ (0.1,0) [0|6553.5] "V"  PC
 SG_ S2P_Lmt16_Under_RModule2_05 : 48|16@1+ (0.1,0) [0|6553.5] "V"  PC

BO_ 2418142790 S2P_Lmt16__06: 8 SBMU
 SG_ S2P_Lmt16_Under_UModule1_06 : 0|16@1+ (0.1,0) [0|6553.5] "V"  PC
 SG_ S2P_Lmt16_Under_RModule1_06 : 16|16@1+ (0.1,0) [0|6553.5] "V"  PC
 SG_ S2P_Lmt16_Under_UModule2_06 : 32|16@1+ (0.1,0) [0|6553.5] "V"  PC
 SG_ S2P_Lmt16_Under_RModule2_06 : 48|16@1+ (0.1,0) [0|6553.5] "V"  PC

BO_ 2418142791 S2P_Lmt16__07: 8 SBMU
 SG_ S2P_Lmt16_Under_UModule1_07 : 0|16@1+ (0.1,0) [0|6553.5] "V"  PC
 SG_ S2P_Lmt16_Under_RModule1_07 : 16|16@1+ (0.1,0) [0|6553.5] "V"  PC
 SG_ S2P_Lmt16_Under_UModule2_07 : 32|16@1+ (0.1,0) [0|6553.5] "V"  PC
 SG_ S2P_Lmt16_Under_RModule2_07 : 48|16@1+ (0.1,0) [0|6553.5] "V"  PC

BO_ 2418142792 S2P_Lmt16__08: 8 SBMU
 SG_ S2P_Lmt16_Under_UModule1_08 : 0|16@1+ (0.1,0) [0|6553.5] "V"  PC
 SG_ S2P_Lmt16_Under_RModule1_08 : 16|16@1+ (0.1,0) [0|6553.5] "V"  PC
 SG_ S2P_Lmt16_Under_UModule2_08 : 32|16@1+ (0.1,0) [0|6553.5] "V"  PC
 SG_ S2P_Lmt16_Under_RModule2_08 : 48|16@1+ (0.1,0) [0|6553.5] "V"  PC

BO_ 2418142793 S2P_Lmt16__09: 8 SBMU
 SG_ S2P_Lmt16_Under_UModule1_09 : 0|16@1+ (0.1,0) [0|6553.5] "V"  PC
 SG_ S2P_Lmt16_Under_RModule1_09 : 16|16@1+ (0.1,0) [0|6553.5] "V"  PC
 SG_ S2P_Lmt16_Under_UModule2_09 : 32|16@1+ (0.1,0) [0|6553.5] "V"  PC
 SG_ S2P_Lmt16_Under_RModule2_09 : 48|16@1+ (0.1,0) [0|6553.5] "V"  PC

BO_ 2418142794 S2P_Lmt16__10: 8 SBMU
 SG_ S2P_Lmt16_Under_UModule1_10 : 0|16@1+ (0.1,0) [0|6553.5] "V"  PC
 SG_ S2P_Lmt16_Under_RModule1_10 : 16|16@1+ (0.1,0) [0|6553.5] "V"  PC
 SG_ S2P_Lmt16_Under_UModule2_10 : 32|16@1+ (0.1,0) [0|6553.5] "V"  PC
 SG_ S2P_Lmt16_Under_RModule2_10 : 48|16@1+ (0.1,0) [0|6553.5] "V"  PC

BO_ 2418142795 S2P_Lmt16__11: 8 SBMU
 SG_ S2P_Lmt16_Under_UModule1_11 : 0|16@1+ (0.1,0) [0|6553.5] "V"  PC
 SG_ S2P_Lmt16_Under_RModule1_11 : 16|16@1+ (0.1,0) [0|6553.5] "V"  PC
 SG_ S2P_Lmt16_Under_UModule2_11 : 32|16@1+ (0.1,0) [0|6553.5] "V"  PC
 SG_ S2P_Lmt16_Under_RModule2_11 : 48|16@1+ (0.1,0) [0|6553.5] "V"  PC

BO_ 2418142796 S2P_Lmt16__12: 8 SBMU
 SG_ S2P_Lmt16_Under_UModule1_12 : 0|16@1+ (0.1,0) [0|6553.5] "V"  PC
 SG_ S2P_Lmt16_Under_RModule1_12 : 16|16@1+ (0.1,0) [0|6553.5] "V"  PC
 SG_ S2P_Lmt16_Under_UModule2_12 : 32|16@1+ (0.1,0) [0|6553.5] "V"  PC
 SG_ S2P_Lmt16_Under_RModule2_12 : 48|16@1+ (0.1,0) [0|6553.5] "V"  PC

BO_ 2418142797 S2P_Lmt16__13: 8 SBMU
 SG_ S2P_Lmt16_Under_UModule1_13 : 0|16@1+ (0.1,0) [0|6553.5] "V"  PC
 SG_ S2P_Lmt16_Under_RModule1_13 : 16|16@1+ (0.1,0) [0|6553.5] "V"  PC
 SG_ S2P_Lmt16_Under_UModule2_13 : 32|16@1+ (0.1,0) [0|6553.5] "V"  PC
 SG_ S2P_Lmt16_Under_RModule2_13 : 48|16@1+ (0.1,0) [0|6553.5] "V"  PC

BO_ 2418142798 S2P_Lmt16__14: 8 SBMU
 SG_ S2P_Lmt16_Under_UModule1_14 : 0|16@1+ (0.1,0) [0|6553.5] "V"  PC
 SG_ S2P_Lmt16_Under_RModule1_14 : 16|16@1+ (0.1,0) [0|6553.5] "V"  PC
 SG_ S2P_Lmt16_Under_UModule2_14 : 32|16@1+ (0.1,0) [0|6553.5] "V"  PC
 SG_ S2P_Lmt16_Under_RModule2_14 : 48|16@1+ (0.1,0) [0|6553.5] "V"  PC

BO_ 2418142799 S2P_Lmt16__15: 8 SBMU
 SG_ S2P_Lmt16_Under_UModule1_15 : 0|16@1+ (0.1,0) [0|6553.5] "V"  PC
 SG_ S2P_Lmt16_Under_RModule1_15 : 16|16@1+ (0.1,0) [0|6553.5] "V"  PC
 SG_ S2P_Lmt16_Under_UModule2_15 : 32|16@1+ (0.1,0) [0|6553.5] "V"  PC
 SG_ S2P_Lmt16_Under_RModule2_15 : 48|16@1+ (0.1,0) [0|6553.5] "V"  PC

BO_ 2418142800 S2P_Lmt16__16: 8 SBMU
 SG_ S2P_Lmt16_Under_UModule1_16 : 0|16@1+ (0.1,0) [0|6553.5] "V"  PC
 SG_ S2P_Lmt16_Under_RModule1_16 : 16|16@1+ (0.1,0) [0|6553.5] "V"  PC
 SG_ S2P_Lmt16_Under_UModule2_16 : 32|16@1+ (0.1,0) [0|6553.5] "V"  PC
 SG_ S2P_Lmt16_Under_RModule2_16 : 48|16@1+ (0.1,0) [0|6553.5] "V"  PC

BO_ 2418142801 S2P_Lmt16__17: 8 SBMU
 SG_ S2P_Lmt16_Under_UModule1_17 : 0|16@1+ (0.1,0) [0|6553.5] "V"  PC
 SG_ S2P_Lmt16_Under_RModule1_17 : 16|16@1+ (0.1,0) [0|6553.5] "V"  PC
 SG_ S2P_Lmt16_Under_UModule2_17 : 32|16@1+ (0.1,0) [0|6553.5] "V"  PC
 SG_ S2P_Lmt16_Under_RModule2_17 : 48|16@1+ (0.1,0) [0|6553.5] "V"  PC

BO_ 2418142802 S2P_Lmt16__18: 8 SBMU
 SG_ S2P_Lmt16_Under_UModule1_18 : 0|16@1+ (0.1,0) [0|6553.5] "V"  PC
 SG_ S2P_Lmt16_Under_RModule1_18 : 16|16@1+ (0.1,0) [0|6553.5] "V"  PC
 SG_ S2P_Lmt16_Under_UModule2_18 : 32|16@1+ (0.1,0) [0|6553.5] "V"  PC
 SG_ S2P_Lmt16_Under_RModule2_18 : 48|16@1+ (0.1,0) [0|6553.5] "V"  PC

BO_ 2418142803 S2P_Lmt16__19: 8 SBMU
 SG_ S2P_Lmt16_Under_UModule1_19 : 0|16@1+ (0.1,0) [0|6553.5] "V"  PC
 SG_ S2P_Lmt16_Under_RModule1_19 : 16|16@1+ (0.1,0) [0|6553.5] "V"  PC
 SG_ S2P_Lmt16_Under_UModule2_19 : 32|16@1+ (0.1,0) [0|6553.5] "V"  PC
 SG_ S2P_Lmt16_Under_RModule2_19 : 48|16@1+ (0.1,0) [0|6553.5] "V"  PC

BO_ 2418142804 S2P_Lmt16__20: 8 SBMU
 SG_ S2P_Lmt16_Under_UModule1_20 : 0|16@1+ (0.1,0) [0|6553.5] "V"  PC
 SG_ S2P_Lmt16_Under_RModule1_20 : 16|16@1+ (0.1,0) [0|6553.5] "V"  PC
 SG_ S2P_Lmt16_Under_UModule2_20 : 32|16@1+ (0.1,0) [0|6553.5] "V"  PC
 SG_ S2P_Lmt16_Under_RModule2_20 : 48|16@1+ (0.1,0) [0|6553.5] "V"  PC

BO_ 2418142805 S2P_Lmt16__21: 8 SBMU
 SG_ S2P_Lmt16_Under_UModule1_21 : 0|16@1+ (0.1,0) [0|6553.5] "V"  PC
 SG_ S2P_Lmt16_Under_RModule1_21 : 16|16@1+ (0.1,0) [0|6553.5] "V"  PC
 SG_ S2P_Lmt16_Under_UModule2_21 : 32|16@1+ (0.1,0) [0|6553.5] "V"  PC
 SG_ S2P_Lmt16_Under_RModule2_21 : 48|16@1+ (0.1,0) [0|6553.5] "V"  PC

BO_ 2418142806 S2P_Lmt16__22: 8 SBMU
 SG_ S2P_Lmt16_Under_UModule1_22 : 0|16@1+ (0.1,0) [0|6553.5] "V"  PC
 SG_ S2P_Lmt16_Under_RModule1_22 : 16|16@1+ (0.1,0) [0|6553.5] "V"  PC
 SG_ S2P_Lmt16_Under_UModule2_22 : 32|16@1+ (0.1,0) [0|6553.5] "V"  PC
 SG_ S2P_Lmt16_Under_RModule2_22 : 48|16@1+ (0.1,0) [0|6553.5] "V"  PC

BO_ 2418142807 S2P_Lmt16__23: 8 SBMU
 SG_ S2P_Lmt16_Under_UModule1_23 : 0|16@1+ (0.1,0) [0|6553.5] "V"  PC
 SG_ S2P_Lmt16_Under_RModule1_23 : 16|16@1+ (0.1,0) [0|6553.5] "V"  PC
 SG_ S2P_Lmt16_Under_UModule2_23 : 32|16@1+ (0.1,0) [0|6553.5] "V"  PC
 SG_ S2P_Lmt16_Under_RModule2_23 : 48|16@1+ (0.1,0) [0|6553.5] "V"  PC

BO_ 2418142808 S2P_Lmt16__24: 8 SBMU
 SG_ S2P_Lmt16_Under_UModule1_24 : 0|16@1+ (0.1,0) [0|6553.5] "V"  PC
 SG_ S2P_Lmt16_Under_RModule1_24 : 16|16@1+ (0.1,0) [0|6553.5] "V"  PC
 SG_ S2P_Lmt16_Under_UModule2_24 : 32|16@1+ (0.1,0) [0|6553.5] "V"  PC
 SG_ S2P_Lmt16_Under_RModule2_24 : 48|16@1+ (0.1,0) [0|6553.5] "V"  PC

BO_ 2418142809 S2P_Lmt16__25: 8 SBMU
 SG_ S2P_Lmt16_Under_UModule1_25 : 0|16@1+ (0.1,0) [0|6553.5] "V"  PC
 SG_ S2P_Lmt16_Under_RModule1_25 : 16|16@1+ (0.1,0) [0|6553.5] "V"  PC
 SG_ S2P_Lmt16_Under_UModule2_25 : 32|16@1+ (0.1,0) [0|6553.5] "V"  PC
 SG_ S2P_Lmt16_Under_RModule2_25 : 48|16@1+ (0.1,0) [0|6553.5] "V"  PC

BO_ 2418142810 S2P_Lmt16__26: 8 SBMU
 SG_ S2P_Lmt16_Under_UModule1_26 : 0|16@1+ (0.1,0) [0|6553.5] "V"  PC
 SG_ S2P_Lmt16_Under_RModule1_26 : 16|16@1+ (0.1,0) [0|6553.5] "V"  PC
 SG_ S2P_Lmt16_Under_UModule2_26 : 32|16@1+ (0.1,0) [0|6553.5] "V"  PC
 SG_ S2P_Lmt16_Under_RModule2_26 : 48|16@1+ (0.1,0) [0|6553.5] "V"  PC

BO_ 2418142811 S2P_Lmt16__27: 8 SBMU
 SG_ S2P_Lmt16_Under_UModule1_27 : 0|16@1+ (0.1,0) [0|6553.5] "V"  PC
 SG_ S2P_Lmt16_Under_RModule1_27 : 16|16@1+ (0.1,0) [0|6553.5] "V"  PC
 SG_ S2P_Lmt16_Under_UModule2_27 : 32|16@1+ (0.1,0) [0|6553.5] "V"  PC
 SG_ S2P_Lmt16_Under_RModule2_27 : 48|16@1+ (0.1,0) [0|6553.5] "V"  PC

BO_ 2418142812 S2P_Lmt16__28: 8 SBMU
 SG_ S2P_Lmt16_Under_UModule1_28 : 0|16@1+ (0.1,0) [0|6553.5] "V"  PC
 SG_ S2P_Lmt16_Under_RModule1_28 : 16|16@1+ (0.1,0) [0|6553.5] "V"  PC
 SG_ S2P_Lmt16_Under_UModule2_28 : 32|16@1+ (0.1,0) [0|6553.5] "V"  PC
 SG_ S2P_Lmt16_Under_RModule2_28 : 48|16@1+ (0.1,0) [0|6553.5] "V"  PC

BO_ 2418142813 S2P_Lmt16__29: 8 SBMU
 SG_ S2P_Lmt16_Under_UModule1_29 : 0|16@1+ (0.1,0) [0|6553.5] "V"  PC
 SG_ S2P_Lmt16_Under_RModule1_29 : 16|16@1+ (0.1,0) [0|6553.5] "V"  PC
 SG_ S2P_Lmt16_Under_UModule2_29 : 32|16@1+ (0.1,0) [0|6553.5] "V"  PC
 SG_ S2P_Lmt16_Under_RModule2_29 : 48|16@1+ (0.1,0) [0|6553.5] "V"  PC

BO_ 2418142814 S2P_Lmt16__30: 8 SBMU
 SG_ S2P_Lmt16_Under_UModule1_30 : 0|16@1+ (0.1,0) [0|6553.5] "V"  PC
 SG_ S2P_Lmt16_Under_RModule1_30 : 16|16@1+ (0.1,0) [0|6553.5] "V"  PC
 SG_ S2P_Lmt16_Under_UModule2_30 : 32|16@1+ (0.1,0) [0|6553.5] "V"  PC
 SG_ S2P_Lmt16_Under_RModule2_30 : 48|16@1+ (0.1,0) [0|6553.5] "V"  PC

BO_ 2418142815 S2P_Lmt16__31: 8 SBMU
 SG_ S2P_Lmt16_Under_UModule1_31 : 0|16@1+ (0.1,0) [0|6553.5] "V"  PC
 SG_ S2P_Lmt16_Under_RModule1_31 : 16|16@1+ (0.1,0) [0|6553.5] "V"  PC
 SG_ S2P_Lmt16_Under_UModule2_31 : 32|16@1+ (0.1,0) [0|6553.5] "V"  PC
 SG_ S2P_Lmt16_Under_RModule2_31 : 48|16@1+ (0.1,0) [0|6553.5] "V"  PC

BO_ 2418142816 S2P_Lmt16__32: 8 SBMU
 SG_ S2P_Lmt16_Under_UModule1_32 : 0|16@1+ (0.1,0) [0|6553.5] "V"  PC
 SG_ S2P_Lmt16_Under_RModule1_32 : 16|16@1+ (0.1,0) [0|6553.5] "V"  PC
 SG_ S2P_Lmt16_Under_UModule2_32 : 32|16@1+ (0.1,0) [0|6553.5] "V"  PC
 SG_ S2P_Lmt16_Under_RModule2_32 : 48|16@1+ (0.1,0) [0|6553.5] "V"  PC

BO_ 2418142817 S2P_Lmt16__33: 8 SBMU
 SG_ S2P_Lmt16_Under_UModule1_33 : 0|16@1+ (0.1,0) [0|6553.5] "V"  PC
 SG_ S2P_Lmt16_Under_RModule1_33 : 16|16@1+ (0.1,0) [0|6553.5] "V"  PC
 SG_ S2P_Lmt16_Under_UModule2_33 : 32|16@1+ (0.1,0) [0|6553.5] "V"  PC
 SG_ S2P_Lmt16_Under_RModule2_33 : 48|16@1+ (0.1,0) [0|6553.5] "V"  PC

BO_ 2418142818 S2P_Lmt16__34: 8 SBMU
 SG_ S2P_Lmt16_Under_UModule1_34 : 0|16@1+ (0.1,0) [0|6553.5] "V"  PC
 SG_ S2P_Lmt16_Under_RModule1_34 : 16|16@1+ (0.1,0) [0|6553.5] "V"  PC
 SG_ S2P_Lmt16_Under_UModule2_34 : 32|16@1+ (0.1,0) [0|6553.5] "V"  PC
 SG_ S2P_Lmt16_Under_RModule2_34 : 48|16@1+ (0.1,0) [0|6553.5] "V"  PC

BO_ 2418142819 S2P_Lmt16__35: 8 SBMU
 SG_ S2P_Lmt16_Under_UModule1_35 : 0|16@1+ (0.1,0) [0|6553.5] "V"  PC
 SG_ S2P_Lmt16_Under_RModule1_35 : 16|16@1+ (0.1,0) [0|6553.5] "V"  PC
 SG_ S2P_Lmt16_Under_UModule2_35 : 32|16@1+ (0.1,0) [0|6553.5] "V"  PC
 SG_ S2P_Lmt16_Under_RModule2_35 : 48|16@1+ (0.1,0) [0|6553.5] "V"  PC

BO_ 2418142820 S2P_Lmt16__36: 8 SBMU
 SG_ S2P_Lmt16_Under_UModule1_36 : 0|16@1+ (0.1,0) [0|6553.5] "V"  PC
 SG_ S2P_Lmt16_Under_RModule1_36 : 16|16@1+ (0.1,0) [0|6553.5] "V"  PC
 SG_ S2P_Lmt16_Under_UModule2_36 : 32|16@1+ (0.1,0) [0|6553.5] "V"  PC
 SG_ S2P_Lmt16_Under_RModule2_36 : 48|16@1+ (0.1,0) [0|6553.5] "V"  PC

BO_ 2418142821 S2P_Lmt16__37: 8 SBMU
 SG_ S2P_Lmt16_Under_UModule1_37 : 0|16@1+ (0.1,0) [0|6553.5] "V"  PC
 SG_ S2P_Lmt16_Under_RModule1_37 : 16|16@1+ (0.1,0) [0|6553.5] "V"  PC
 SG_ S2P_Lmt16_Under_UModule2_37 : 32|16@1+ (0.1,0) [0|6553.5] "V"  PC
 SG_ S2P_Lmt16_Under_RModule2_37 : 48|16@1+ (0.1,0) [0|6553.5] "V"  PC

BO_ 2418142822 S2P_Lmt16__38: 8 SBMU
 SG_ S2P_Lmt16_Under_UModule1_38 : 0|16@1+ (0.1,0) [0|6553.5] "V"  PC
 SG_ S2P_Lmt16_Under_RModule1_38 : 16|16@1+ (0.1,0) [0|6553.5] "V"  PC
 SG_ S2P_Lmt16_Under_UModule2_38 : 32|16@1+ (0.1,0) [0|6553.5] "V"  PC
 SG_ S2P_Lmt16_Under_RModule2_38 : 48|16@1+ (0.1,0) [0|6553.5] "V"  PC

BO_ 2418142823 S2P_Lmt16__39: 8 SBMU
 SG_ S2P_Lmt16_Under_UModule1_39 : 0|16@1+ (0.1,0) [0|6553.5] "V"  PC
 SG_ S2P_Lmt16_Under_RModule1_39 : 16|16@1+ (0.1,0) [0|6553.5] "V"  PC
 SG_ S2P_Lmt16_Under_UModule2_39 : 32|16@1+ (0.1,0) [0|6553.5] "V"  PC
 SG_ S2P_Lmt16_Under_RModule2_39 : 48|16@1+ (0.1,0) [0|6553.5] "V"  PC

BO_ 2418142824 S2P_Lmt16__40: 8 SBMU
 SG_ S2P_Lmt16_Under_UModule1_40 : 0|16@1+ (0.1,0) [0|6553.5] "V"  PC
 SG_ S2P_Lmt16_Under_RModule1_40 : 16|16@1+ (0.1,0) [0|6553.5] "V"  PC
 SG_ S2P_Lmt16_Under_UModule2_40 : 32|16@1+ (0.1,0) [0|6553.5] "V"  PC
 SG_ S2P_Lmt16_Under_RModule2_40 : 48|16@1+ (0.1,0) [0|6553.5] "V"  PC

BO_ 2418142825 S2P_Lmt16__41: 8 SBMU
 SG_ S2P_Lmt16_Under_UModule1_41 : 0|16@1+ (0.1,0) [0|6553.5] "V"  PC
 SG_ S2P_Lmt16_Under_RModule1_41 : 16|16@1+ (0.1,0) [0|6553.5] "V"  PC
 SG_ S2P_Lmt16_Under_UModule2_41 : 32|16@1+ (0.1,0) [0|6553.5] "V"  PC
 SG_ S2P_Lmt16_Under_RModule2_41 : 48|16@1+ (0.1,0) [0|6553.5] "V"  PC

BO_ 2418142826 S2P_Lmt16__42: 8 SBMU
 SG_ S2P_Lmt16_Under_UModule1_42 : 0|16@1+ (0.1,0) [0|6553.5] "V"  PC
 SG_ S2P_Lmt16_Under_RModule1_42 : 16|16@1+ (0.1,0) [0|6553.5] "V"  PC
 SG_ S2P_Lmt16_Under_UModule2_42 : 32|16@1+ (0.1,0) [0|6553.5] "V"  PC
 SG_ S2P_Lmt16_Under_RModule2_42 : 48|16@1+ (0.1,0) [0|6553.5] "V"  PC

BO_ 2418142827 S2P_Lmt16__43: 8 SBMU
 SG_ S2P_Lmt16_Under_UModule1_43 : 0|16@1+ (0.1,0) [0|6553.5] "V"  PC
 SG_ S2P_Lmt16_Under_RModule1_43 : 16|16@1+ (0.1,0) [0|6553.5] "V"  PC
 SG_ S2P_Lmt16_Under_UModule2_43 : 32|16@1+ (0.1,0) [0|6553.5] "V"  PC
 SG_ S2P_Lmt16_Under_RModule2_43 : 48|16@1+ (0.1,0) [0|6553.5] "V"  PC

BO_ 2418142828 S2P_Lmt16__44: 8 SBMU
 SG_ S2P_Lmt16_Under_UModule1_44 : 0|16@1+ (0.1,0) [0|6553.5] "V"  PC
 SG_ S2P_Lmt16_Under_RModule1_44 : 16|16@1+ (0.1,0) [0|6553.5] "V"  PC
 SG_ S2P_Lmt16_Under_UModule2_44 : 32|16@1+ (0.1,0) [0|6553.5] "V"  PC
 SG_ S2P_Lmt16_Under_RModule2_44 : 48|16@1+ (0.1,0) [0|6553.5] "V"  PC

BO_ 2418142829 S2P_Lmt16__45: 8 SBMU
 SG_ S2P_Lmt16_Under_UModule1_45 : 0|16@1+ (0.1,0) [0|6553.5] "V"  PC
 SG_ S2P_Lmt16_Under_RModule1_45 : 16|16@1+ (0.1,0) [0|6553.5] "V"  PC
 SG_ S2P_Lmt16_Under_UModule2_45 : 32|16@1+ (0.1,0) [0|6553.5] "V"  PC
 SG_ S2P_Lmt16_Under_RModule2_45 : 48|16@1+ (0.1,0) [0|6553.5] "V"  PC

BO_ 2418142830 S2P_Lmt16__46: 8 SBMU
 SG_ S2P_Lmt16_Under_UModule1_46 : 0|16@1+ (0.1,0) [0|6553.5] "V"  PC
 SG_ S2P_Lmt16_Under_RModule1_46 : 16|16@1+ (0.1,0) [0|6553.5] "V"  PC
 SG_ S2P_Lmt16_Under_UModule2_46 : 32|16@1+ (0.1,0) [0|6553.5] "V"  PC
 SG_ S2P_Lmt16_Under_RModule2_46 : 48|16@1+ (0.1,0) [0|6553.5] "V"  PC

BO_ 2418142831 S2P_Lmt16__47: 8 SBMU
 SG_ S2P_Lmt16_Under_UModule1_47 : 0|16@1+ (0.1,0) [0|6553.5] "V"  PC
 SG_ S2P_Lmt16_Under_RModule1_47 : 16|16@1+ (0.1,0) [0|6553.5] "V"  PC
 SG_ S2P_Lmt16_Under_UModule2_47 : 32|16@1+ (0.1,0) [0|6553.5] "V"  PC
 SG_ S2P_Lmt16_Under_RModule2_47 : 48|16@1+ (0.1,0) [0|6553.5] "V"  PC

BO_ 2418142832 S2P_Lmt16__48: 8 SBMU
 SG_ S2P_Lmt16_Under_UModule1_48 : 0|16@1+ (0.1,0) [0|6553.5] "V"  PC
 SG_ S2P_Lmt16_Under_RModule1_48 : 16|16@1+ (0.1,0) [0|6553.5] "V"  PC
 SG_ S2P_Lmt16_Under_UModule2_48 : 32|16@1+ (0.1,0) [0|6553.5] "V"  PC
 SG_ S2P_Lmt16_Under_RModule2_48 : 48|16@1+ (0.1,0) [0|6553.5] "V"  PC

BO_ 2418142833 S2P_Lmt16__49: 8 SBMU
 SG_ S2P_Lmt16_Under_UModule1_49 : 0|16@1+ (0.1,0) [0|6553.5] "V"  PC
 SG_ S2P_Lmt16_Under_RModule1_49 : 16|16@1+ (0.1,0) [0|6553.5] "V"  PC
 SG_ S2P_Lmt16_Under_UModule2_49 : 32|16@1+ (0.1,0) [0|6553.5] "V"  PC
 SG_ S2P_Lmt16_Under_RModule2_49 : 48|16@1+ (0.1,0) [0|6553.5] "V"  PC

BO_ 2418142834 S2P_Lmt16__50: 8 SBMU
 SG_ S2P_Lmt16_Under_UModule1_50 : 0|16@1+ (0.1,0) [0|6553.5] "V"  PC
 SG_ S2P_Lmt16_Under_RModule1_50 : 16|16@1+ (0.1,0) [0|6553.5] "V"  PC
 SG_ S2P_Lmt16_Under_UModule2_50 : 32|16@1+ (0.1,0) [0|6553.5] "V"  PC
 SG_ S2P_Lmt16_Under_RModule2_50 : 48|16@1+ (0.1,0) [0|6553.5] "V"  PC

BO_ 2418142835 S2P_Lmt16__51: 8 SBMU
 SG_ S2P_Lmt16_Under_UModule1_51 : 0|16@1+ (0.1,0) [0|6553.5] "V"  PC
 SG_ S2P_Lmt16_Under_RModule1_51 : 16|16@1+ (0.1,0) [0|6553.5] "V"  PC
 SG_ S2P_Lmt16_Under_UModule2_51 : 32|16@1+ (0.1,0) [0|6553.5] "V"  PC
 SG_ S2P_Lmt16_Under_RModule2_51 : 48|16@1+ (0.1,0) [0|6553.5] "V"  PC

BO_ 2418142836 S2P_Lmt16__52: 8 SBMU
 SG_ S2P_Lmt16_Under_UModule1_52 : 0|16@1+ (0.1,0) [0|6553.5] "V"  PC
 SG_ S2P_Lmt16_Under_RModule1_52 : 16|16@1+ (0.1,0) [0|6553.5] "V"  PC
 SG_ S2P_Lmt16_Under_UModule2_52 : 32|16@1+ (0.1,0) [0|6553.5] "V"  PC
 SG_ S2P_Lmt16_Under_RModule2_52 : 48|16@1+ (0.1,0) [0|6553.5] "V"  PC

BO_ 2418142837 S2P_Lmt16__53: 8 SBMU
 SG_ S2P_Lmt16_Under_UModule1_53 : 0|16@1+ (0.1,0) [0|6553.5] "V"  PC
 SG_ S2P_Lmt16_Under_RModule1_53 : 16|16@1+ (0.1,0) [0|6553.5] "V"  PC
 SG_ S2P_Lmt16_Under_UModule2_53 : 32|16@1+ (0.1,0) [0|6553.5] "V"  PC
 SG_ S2P_Lmt16_Under_RModule2_53 : 48|16@1+ (0.1,0) [0|6553.5] "V"  PC

BO_ 2418142838 S2P_Lmt16__54: 8 SBMU
 SG_ S2P_Lmt16_Under_UModule1_54 : 0|16@1+ (0.1,0) [0|6553.5] "V"  PC
 SG_ S2P_Lmt16_Under_RModule1_54 : 16|16@1+ (0.1,0) [0|6553.5] "V"  PC
 SG_ S2P_Lmt16_Under_UModule2_54 : 32|16@1+ (0.1,0) [0|6553.5] "V"  PC
 SG_ S2P_Lmt16_Under_RModule2_54 : 48|16@1+ (0.1,0) [0|6553.5] "V"  PC

BO_ 2418142839 S2P_Lmt16__55: 8 SBMU
 SG_ S2P_Lmt16_Under_UModule1_55 : 0|16@1+ (0.1,0) [0|6553.5] "V"  PC
 SG_ S2P_Lmt16_Under_RModule1_55 : 16|16@1+ (0.1,0) [0|6553.5] "V"  PC
 SG_ S2P_Lmt16_Under_UModule2_55 : 32|16@1+ (0.1,0) [0|6553.5] "V"  PC
 SG_ S2P_Lmt16_Under_RModule2_55 : 48|16@1+ (0.1,0) [0|6553.5] "V"  PC

BO_ 2418142840 S2P_Lmt16__56: 8 SBMU
 SG_ S2P_Lmt16_Under_UModule1_56 : 0|16@1+ (0.1,0) [0|6553.5] "V"  PC
 SG_ S2P_Lmt16_Under_RModule1_56 : 16|16@1+ (0.1,0) [0|6553.5] "V"  PC
 SG_ S2P_Lmt16_Under_UModule2_56 : 32|16@1+ (0.1,0) [0|6553.5] "V"  PC
 SG_ S2P_Lmt16_Under_RModule2_56 : 48|16@1+ (0.1,0) [0|6553.5] "V"  PC

BO_ 2418142841 S2P_Lmt16__57: 8 SBMU
 SG_ S2P_Lmt16_Under_UModule1_57 : 0|16@1+ (0.1,0) [0|6553.5] "V"  PC
 SG_ S2P_Lmt16_Under_RModule1_57 : 16|16@1+ (0.1,0) [0|6553.5] "V"  PC
 SG_ S2P_Lmt16_Under_UModule2_57 : 32|16@1+ (0.1,0) [0|6553.5] "V"  PC
 SG_ S2P_Lmt16_Under_RModule2_57 : 48|16@1+ (0.1,0) [0|6553.5] "V"  PC

BO_ 2418142842 S2P_Lmt16__58: 8 SBMU
 SG_ S2P_Lmt16_Under_UModule1_58 : 0|16@1+ (0.1,0) [0|6553.5] "V"  PC
 SG_ S2P_Lmt16_Under_RModule1_58 : 16|16@1+ (0.1,0) [0|6553.5] "V"  PC
 SG_ S2P_Lmt16_Under_UModule2_58 : 32|16@1+ (0.1,0) [0|6553.5] "V"  PC
 SG_ S2P_Lmt16_Under_RModule2_58 : 48|16@1+ (0.1,0) [0|6553.5] "V"  PC

BO_ 2418142843 S2P_Lmt16__59: 8 SBMU
 SG_ S2P_Lmt16_Under_UModule1_59 : 0|16@1+ (0.1,0) [0|6553.5] "V"  PC
 SG_ S2P_Lmt16_Under_RModule1_59 : 16|16@1+ (0.1,0) [0|6553.5] "V"  PC
 SG_ S2P_Lmt16_Under_UModule2_59 : 32|16@1+ (0.1,0) [0|6553.5] "V"  PC
 SG_ S2P_Lmt16_Under_RModule2_59 : 48|16@1+ (0.1,0) [0|6553.5] "V"  PC

BO_ 2418142844 S2P_Lmt16__60: 8 SBMU
 SG_ S2P_Lmt16_Under_UModule1_60 : 0|16@1+ (0.1,0) [0|6553.5] "V"  PC
 SG_ S2P_Lmt16_Under_RModule1_60 : 16|16@1+ (0.1,0) [0|6553.5] "V"  PC
 SG_ S2P_Lmt16_Under_UModule2_60 : 32|16@1+ (0.1,0) [0|6553.5] "V"  PC
 SG_ S2P_Lmt16_Under_RModule2_60 : 48|16@1+ (0.1,0) [0|6553.5] "V"  PC

BO_ 2418142845 S2P_Lmt16__61: 8 SBMU
 SG_ S2P_Lmt16_Under_UModule1_61 : 0|16@1+ (0.1,0) [0|6553.5] "V"  PC
 SG_ S2P_Lmt16_Under_RModule1_61 : 16|16@1+ (0.1,0) [0|6553.5] "V"  PC
 SG_ S2P_Lmt16_Under_UModule2_61 : 32|16@1+ (0.1,0) [0|6553.5] "V"  PC
 SG_ S2P_Lmt16_Under_RModule2_61 : 48|16@1+ (0.1,0) [0|6553.5] "V"  PC

BO_ 2418142846 S2P_Lmt16__62: 8 SBMU
 SG_ S2P_Lmt16_Under_UModule1_62 : 0|16@1+ (0.1,0) [0|6553.5] "V"  PC
 SG_ S2P_Lmt16_Under_RModule1_62 : 16|16@1+ (0.1,0) [0|6553.5] "V"  PC
 SG_ S2P_Lmt16_Under_UModule2_62 : 32|16@1+ (0.1,0) [0|6553.5] "V"  PC
 SG_ S2P_Lmt16_Under_RModule2_62 : 48|16@1+ (0.1,0) [0|6553.5] "V"  PC

BO_ 2418142847 S2P_Lmt16__63: 8 SBMU
 SG_ S2P_Lmt16_Under_UModule1_63 : 0|16@1+ (0.1,0) [0|6553.5] "V"  PC
 SG_ S2P_Lmt16_Under_RModule1_63 : 16|16@1+ (0.1,0) [0|6553.5] "V"  PC
 SG_ S2P_Lmt16_Under_UModule2_63 : 32|16@1+ (0.1,0) [0|6553.5] "V"  PC
 SG_ S2P_Lmt16_Under_RModule2_63 : 48|16@1+ (0.1,0) [0|6553.5] "V"  PC

BO_ 2418208321 S2P_Lmt17__01: 8 SBMU
 SG_ S2P_Lmt17_Over_UModule3_01 : 0|16@1+ (0.1,0) [0|6553.5] "V"  PC
 SG_ S2P_Lmt17_Under_UModule3_01 : 16|16@1+ (0.1,0) [0|6553.5] "V"  PC
 SG_ S2P_Lmt17_Over_UModule4_01 : 32|16@1+ (0.1,0) [0|6553.5] "V"  PC
 SG_ S2P_Lmt17_Under_UModule4_01 : 48|16@1+ (0.1,0) [0|6553.5] "V"  PC

BO_ 2418208322 S2P_Lmt17__02: 8 SBMU
 SG_ S2P_Lmt17_Over_UModule3_02 : 0|16@1+ (0.1,0) [0|6553.5] "V"  PC
 SG_ S2P_Lmt17_Under_UModule3_02 : 16|16@1+ (0.1,0) [0|6553.5] "V"  PC
 SG_ S2P_Lmt17_Over_UModule4_02 : 32|16@1+ (0.1,0) [0|6553.5] "V"  PC
 SG_ S2P_Lmt17_Under_UModule4_02 : 48|16@1+ (0.1,0) [0|6553.5] "V"  PC

BO_ 2418208323 S2P_Lmt17__03: 8 SBMU
 SG_ S2P_Lmt17_Over_UModule3_03 : 0|16@1+ (0.1,0) [0|6553.5] "V"  PC
 SG_ S2P_Lmt17_Under_UModule3_03 : 16|16@1+ (0.1,0) [0|6553.5] "V"  PC
 SG_ S2P_Lmt17_Over_UModule4_03 : 32|16@1+ (0.1,0) [0|6553.5] "V"  PC
 SG_ S2P_Lmt17_Under_UModule4_03 : 48|16@1+ (0.1,0) [0|6553.5] "V"  PC

BO_ 2418208324 S2P_Lmt17__04: 8 SBMU
 SG_ S2P_Lmt17_Over_UModule3_04 : 0|16@1+ (0.1,0) [0|6553.5] "V"  PC
 SG_ S2P_Lmt17_Under_UModule3_04 : 16|16@1+ (0.1,0) [0|6553.5] "V"  PC
 SG_ S2P_Lmt17_Over_UModule4_04 : 32|16@1+ (0.1,0) [0|6553.5] "V"  PC
 SG_ S2P_Lmt17_Under_UModule4_04 : 48|16@1+ (0.1,0) [0|6553.5] "V"  PC

BO_ 2418208325 S2P_Lmt17__05: 8 SBMU
 SG_ S2P_Lmt17_Over_UModule3_05 : 0|16@1+ (0.1,0) [0|6553.5] "V"  PC
 SG_ S2P_Lmt17_Under_UModule3_05 : 16|16@1+ (0.1,0) [0|6553.5] "V"  PC
 SG_ S2P_Lmt17_Over_UModule4_05 : 32|16@1+ (0.1,0) [0|6553.5] "V"  PC
 SG_ S2P_Lmt17_Under_UModule4_05 : 48|16@1+ (0.1,0) [0|6553.5] "V"  PC

BO_ 2418208326 S2P_Lmt17__06: 8 SBMU
 SG_ S2P_Lmt17_Over_UModule3_06 : 0|16@1+ (0.1,0) [0|6553.5] "V"  PC
 SG_ S2P_Lmt17_Under_UModule3_06 : 16|16@1+ (0.1,0) [0|6553.5] "V"  PC
 SG_ S2P_Lmt17_Over_UModule4_06 : 32|16@1+ (0.1,0) [0|6553.5] "V"  PC
 SG_ S2P_Lmt17_Under_UModule4_06 : 48|16@1+ (0.1,0) [0|6553.5] "V"  PC

BO_ 2418208327 S2P_Lmt17__07: 8 SBMU
 SG_ S2P_Lmt17_Over_UModule3_07 : 0|16@1+ (0.1,0) [0|6553.5] "V"  PC
 SG_ S2P_Lmt17_Under_UModule3_07 : 16|16@1+ (0.1,0) [0|6553.5] "V"  PC
 SG_ S2P_Lmt17_Over_UModule4_07 : 32|16@1+ (0.1,0) [0|6553.5] "V"  PC
 SG_ S2P_Lmt17_Under_UModule4_07 : 48|16@1+ (0.1,0) [0|6553.5] "V"  PC

BO_ 2418208328 S2P_Lmt17__08: 8 SBMU
 SG_ S2P_Lmt17_Over_UModule3_08 : 0|16@1+ (0.1,0) [0|6553.5] "V"  PC
 SG_ S2P_Lmt17_Under_UModule3_08 : 16|16@1+ (0.1,0) [0|6553.5] "V"  PC
 SG_ S2P_Lmt17_Over_UModule4_08 : 32|16@1+ (0.1,0) [0|6553.5] "V"  PC
 SG_ S2P_Lmt17_Under_UModule4_08 : 48|16@1+ (0.1,0) [0|6553.5] "V"  PC

BO_ 2418208329 S2P_Lmt17__09: 8 SBMU
 SG_ S2P_Lmt17_Over_UModule3_09 : 0|16@1+ (0.1,0) [0|6553.5] "V"  PC
 SG_ S2P_Lmt17_Under_UModule3_09 : 16|16@1+ (0.1,0) [0|6553.5] "V"  PC
 SG_ S2P_Lmt17_Over_UModule4_09 : 32|16@1+ (0.1,0) [0|6553.5] "V"  PC
 SG_ S2P_Lmt17_Under_UModule4_09 : 48|16@1+ (0.1,0) [0|6553.5] "V"  PC

BO_ 2418208330 S2P_Lmt17__10: 8 SBMU
 SG_ S2P_Lmt17_Over_UModule3_10 : 0|16@1+ (0.1,0) [0|6553.5] "V"  PC
 SG_ S2P_Lmt17_Under_UModule3_10 : 16|16@1+ (0.1,0) [0|6553.5] "V"  PC
 SG_ S2P_Lmt17_Over_UModule4_10 : 32|16@1+ (0.1,0) [0|6553.5] "V"  PC
 SG_ S2P_Lmt17_Under_UModule4_10 : 48|16@1+ (0.1,0) [0|6553.5] "V"  PC

BO_ 2418208331 S2P_Lmt17__11: 8 SBMU
 SG_ S2P_Lmt17_Over_UModule3_11 : 0|16@1+ (0.1,0) [0|6553.5] "V"  PC
 SG_ S2P_Lmt17_Under_UModule3_11 : 16|16@1+ (0.1,0) [0|6553.5] "V"  PC
 SG_ S2P_Lmt17_Over_UModule4_11 : 32|16@1+ (0.1,0) [0|6553.5] "V"  PC
 SG_ S2P_Lmt17_Under_UModule4_11 : 48|16@1+ (0.1,0) [0|6553.5] "V"  PC

BO_ 2418208332 S2P_Lmt17__12: 8 SBMU
 SG_ S2P_Lmt17_Over_UModule3_12 : 0|16@1+ (0.1,0) [0|6553.5] "V"  PC
 SG_ S2P_Lmt17_Under_UModule3_12 : 16|16@1+ (0.1,0) [0|6553.5] "V"  PC
 SG_ S2P_Lmt17_Over_UModule4_12 : 32|16@1+ (0.1,0) [0|6553.5] "V"  PC
 SG_ S2P_Lmt17_Under_UModule4_12 : 48|16@1+ (0.1,0) [0|6553.5] "V"  PC

BO_ 2418208333 S2P_Lmt17__13: 8 SBMU
 SG_ S2P_Lmt17_Over_UModule3_13 : 0|16@1+ (0.1,0) [0|6553.5] "V"  PC
 SG_ S2P_Lmt17_Under_UModule3_13 : 16|16@1+ (0.1,0) [0|6553.5] "V"  PC
 SG_ S2P_Lmt17_Over_UModule4_13 : 32|16@1+ (0.1,0) [0|6553.5] "V"  PC
 SG_ S2P_Lmt17_Under_UModule4_13 : 48|16@1+ (0.1,0) [0|6553.5] "V"  PC

BO_ 2418208334 S2P_Lmt17__14: 8 SBMU
 SG_ S2P_Lmt17_Over_UModule3_14 : 0|16@1+ (0.1,0) [0|6553.5] "V"  PC
 SG_ S2P_Lmt17_Under_UModule3_14 : 16|16@1+ (0.1,0) [0|6553.5] "V"  PC
 SG_ S2P_Lmt17_Over_UModule4_14 : 32|16@1+ (0.1,0) [0|6553.5] "V"  PC
 SG_ S2P_Lmt17_Under_UModule4_14 : 48|16@1+ (0.1,0) [0|6553.5] "V"  PC

BO_ 2418208335 S2P_Lmt17__15: 8 SBMU
 SG_ S2P_Lmt17_Over_UModule3_15 : 0|16@1+ (0.1,0) [0|6553.5] "V"  PC
 SG_ S2P_Lmt17_Under_UModule3_15 : 16|16@1+ (0.1,0) [0|6553.5] "V"  PC
 SG_ S2P_Lmt17_Over_UModule4_15 : 32|16@1+ (0.1,0) [0|6553.5] "V"  PC
 SG_ S2P_Lmt17_Under_UModule4_15 : 48|16@1+ (0.1,0) [0|6553.5] "V"  PC

BO_ 2418208336 S2P_Lmt17__16: 8 SBMU
 SG_ S2P_Lmt17_Over_UModule3_16 : 0|16@1+ (0.1,0) [0|6553.5] "V"  PC
 SG_ S2P_Lmt17_Under_UModule3_16 : 16|16@1+ (0.1,0) [0|6553.5] "V"  PC
 SG_ S2P_Lmt17_Over_UModule4_16 : 32|16@1+ (0.1,0) [0|6553.5] "V"  PC
 SG_ S2P_Lmt17_Under_UModule4_16 : 48|16@1+ (0.1,0) [0|6553.5] "V"  PC

BO_ 2418208337 S2P_Lmt17__17: 8 SBMU
 SG_ S2P_Lmt17_Over_UModule3_17 : 0|16@1+ (0.1,0) [0|6553.5] "V"  PC
 SG_ S2P_Lmt17_Under_UModule3_17 : 16|16@1+ (0.1,0) [0|6553.5] "V"  PC
 SG_ S2P_Lmt17_Over_UModule4_17 : 32|16@1+ (0.1,0) [0|6553.5] "V"  PC
 SG_ S2P_Lmt17_Under_UModule4_17 : 48|16@1+ (0.1,0) [0|6553.5] "V"  PC

BO_ 2418208338 S2P_Lmt17__18: 8 SBMU
 SG_ S2P_Lmt17_Over_UModule3_18 : 0|16@1+ (0.1,0) [0|6553.5] "V"  PC
 SG_ S2P_Lmt17_Under_UModule3_18 : 16|16@1+ (0.1,0) [0|6553.5] "V"  PC
 SG_ S2P_Lmt17_Over_UModule4_18 : 32|16@1+ (0.1,0) [0|6553.5] "V"  PC
 SG_ S2P_Lmt17_Under_UModule4_18 : 48|16@1+ (0.1,0) [0|6553.5] "V"  PC

BO_ 2418208339 S2P_Lmt17__19: 8 SBMU
 SG_ S2P_Lmt17_Over_UModule3_19 : 0|16@1+ (0.1,0) [0|6553.5] "V"  PC
 SG_ S2P_Lmt17_Under_UModule3_19 : 16|16@1+ (0.1,0) [0|6553.5] "V"  PC
 SG_ S2P_Lmt17_Over_UModule4_19 : 32|16@1+ (0.1,0) [0|6553.5] "V"  PC
 SG_ S2P_Lmt17_Under_UModule4_19 : 48|16@1+ (0.1,0) [0|6553.5] "V"  PC

BO_ 2418208340 S2P_Lmt17__20: 8 SBMU
 SG_ S2P_Lmt17_Over_UModule3_20 : 0|16@1+ (0.1,0) [0|6553.5] "V"  PC
 SG_ S2P_Lmt17_Under_UModule3_20 : 16|16@1+ (0.1,0) [0|6553.5] "V"  PC
 SG_ S2P_Lmt17_Over_UModule4_20 : 32|16@1+ (0.1,0) [0|6553.5] "V"  PC
 SG_ S2P_Lmt17_Under_UModule4_20 : 48|16@1+ (0.1,0) [0|6553.5] "V"  PC

BO_ 2418208341 S2P_Lmt17__21: 8 SBMU
 SG_ S2P_Lmt17_Over_UModule3_21 : 0|16@1+ (0.1,0) [0|6553.5] "V"  PC
 SG_ S2P_Lmt17_Under_UModule3_21 : 16|16@1+ (0.1,0) [0|6553.5] "V"  PC
 SG_ S2P_Lmt17_Over_UModule4_21 : 32|16@1+ (0.1,0) [0|6553.5] "V"  PC
 SG_ S2P_Lmt17_Under_UModule4_21 : 48|16@1+ (0.1,0) [0|6553.5] "V"  PC

BO_ 2418208342 S2P_Lmt17__22: 8 SBMU
 SG_ S2P_Lmt17_Over_UModule3_22 : 0|16@1+ (0.1,0) [0|6553.5] "V"  PC
 SG_ S2P_Lmt17_Under_UModule3_22 : 16|16@1+ (0.1,0) [0|6553.5] "V"  PC
 SG_ S2P_Lmt17_Over_UModule4_22 : 32|16@1+ (0.1,0) [0|6553.5] "V"  PC
 SG_ S2P_Lmt17_Under_UModule4_22 : 48|16@1+ (0.1,0) [0|6553.5] "V"  PC

BO_ 2418208343 S2P_Lmt17__23: 8 SBMU
 SG_ S2P_Lmt17_Over_UModule3_23 : 0|16@1+ (0.1,0) [0|6553.5] "V"  PC
 SG_ S2P_Lmt17_Under_UModule3_23 : 16|16@1+ (0.1,0) [0|6553.5] "V"  PC
 SG_ S2P_Lmt17_Over_UModule4_23 : 32|16@1+ (0.1,0) [0|6553.5] "V"  PC
 SG_ S2P_Lmt17_Under_UModule4_23 : 48|16@1+ (0.1,0) [0|6553.5] "V"  PC

BO_ 2418208344 S2P_Lmt17__24: 8 SBMU
 SG_ S2P_Lmt17_Over_UModule3_24 : 0|16@1+ (0.1,0) [0|6553.5] "V"  PC
 SG_ S2P_Lmt17_Under_UModule3_24 : 16|16@1+ (0.1,0) [0|6553.5] "V"  PC
 SG_ S2P_Lmt17_Over_UModule4_24 : 32|16@1+ (0.1,0) [0|6553.5] "V"  PC
 SG_ S2P_Lmt17_Under_UModule4_24 : 48|16@1+ (0.1,0) [0|6553.5] "V"  PC

BO_ 2418208345 S2P_Lmt17__25: 8 SBMU
 SG_ S2P_Lmt17_Over_UModule3_25 : 0|16@1+ (0.1,0) [0|6553.5] "V"  PC
 SG_ S2P_Lmt17_Under_UModule3_25 : 16|16@1+ (0.1,0) [0|6553.5] "V"  PC
 SG_ S2P_Lmt17_Over_UModule4_25 : 32|16@1+ (0.1,0) [0|6553.5] "V"  PC
 SG_ S2P_Lmt17_Under_UModule4_25 : 48|16@1+ (0.1,0) [0|6553.5] "V"  PC

BO_ 2418208346 S2P_Lmt17__26: 8 SBMU
 SG_ S2P_Lmt17_Over_UModule3_26 : 0|16@1+ (0.1,0) [0|6553.5] "V"  PC
 SG_ S2P_Lmt17_Under_UModule3_26 : 16|16@1+ (0.1,0) [0|6553.5] "V"  PC
 SG_ S2P_Lmt17_Over_UModule4_26 : 32|16@1+ (0.1,0) [0|6553.5] "V"  PC
 SG_ S2P_Lmt17_Under_UModule4_26 : 48|16@1+ (0.1,0) [0|6553.5] "V"  PC

BO_ 2418208347 S2P_Lmt17__27: 8 SBMU
 SG_ S2P_Lmt17_Over_UModule3_27 : 0|16@1+ (0.1,0) [0|6553.5] "V"  PC
 SG_ S2P_Lmt17_Under_UModule3_27 : 16|16@1+ (0.1,0) [0|6553.5] "V"  PC
 SG_ S2P_Lmt17_Over_UModule4_27 : 32|16@1+ (0.1,0) [0|6553.5] "V"  PC
 SG_ S2P_Lmt17_Under_UModule4_27 : 48|16@1+ (0.1,0) [0|6553.5] "V"  PC

BO_ 2418208348 S2P_Lmt17__28: 8 SBMU
 SG_ S2P_Lmt17_Over_UModule3_28 : 0|16@1+ (0.1,0) [0|6553.5] "V"  PC
 SG_ S2P_Lmt17_Under_UModule3_28 : 16|16@1+ (0.1,0) [0|6553.5] "V"  PC
 SG_ S2P_Lmt17_Over_UModule4_28 : 32|16@1+ (0.1,0) [0|6553.5] "V"  PC
 SG_ S2P_Lmt17_Under_UModule4_28 : 48|16@1+ (0.1,0) [0|6553.5] "V"  PC

BO_ 2418208349 S2P_Lmt17__29: 8 SBMU
 SG_ S2P_Lmt17_Over_UModule3_29 : 0|16@1+ (0.1,0) [0|6553.5] "V"  PC
 SG_ S2P_Lmt17_Under_UModule3_29 : 16|16@1+ (0.1,0) [0|6553.5] "V"  PC
 SG_ S2P_Lmt17_Over_UModule4_29 : 32|16@1+ (0.1,0) [0|6553.5] "V"  PC
 SG_ S2P_Lmt17_Under_UModule4_29 : 48|16@1+ (0.1,0) [0|6553.5] "V"  PC

BO_ 2418208350 S2P_Lmt17__30: 8 SBMU
 SG_ S2P_Lmt17_Over_UModule3_30 : 0|16@1+ (0.1,0) [0|6553.5] "V"  PC
 SG_ S2P_Lmt17_Under_UModule3_30 : 16|16@1+ (0.1,0) [0|6553.5] "V"  PC
 SG_ S2P_Lmt17_Over_UModule4_30 : 32|16@1+ (0.1,0) [0|6553.5] "V"  PC
 SG_ S2P_Lmt17_Under_UModule4_30 : 48|16@1+ (0.1,0) [0|6553.5] "V"  PC

BO_ 2418208351 S2P_Lmt17__31: 8 SBMU
 SG_ S2P_Lmt17_Over_UModule3_31 : 0|16@1+ (0.1,0) [0|6553.5] "V"  PC
 SG_ S2P_Lmt17_Under_UModule3_31 : 16|16@1+ (0.1,0) [0|6553.5] "V"  PC
 SG_ S2P_Lmt17_Over_UModule4_31 : 32|16@1+ (0.1,0) [0|6553.5] "V"  PC
 SG_ S2P_Lmt17_Under_UModule4_31 : 48|16@1+ (0.1,0) [0|6553.5] "V"  PC

BO_ 2418208352 S2P_Lmt17__32: 8 SBMU
 SG_ S2P_Lmt17_Over_UModule3_32 : 0|16@1+ (0.1,0) [0|6553.5] "V"  PC
 SG_ S2P_Lmt17_Under_UModule3_32 : 16|16@1+ (0.1,0) [0|6553.5] "V"  PC
 SG_ S2P_Lmt17_Over_UModule4_32 : 32|16@1+ (0.1,0) [0|6553.5] "V"  PC
 SG_ S2P_Lmt17_Under_UModule4_32 : 48|16@1+ (0.1,0) [0|6553.5] "V"  PC

BO_ 2418208353 S2P_Lmt17__33: 8 SBMU
 SG_ S2P_Lmt17_Over_UModule3_33 : 0|16@1+ (0.1,0) [0|6553.5] "V"  PC
 SG_ S2P_Lmt17_Under_UModule3_33 : 16|16@1+ (0.1,0) [0|6553.5] "V"  PC
 SG_ S2P_Lmt17_Over_UModule4_33 : 32|16@1+ (0.1,0) [0|6553.5] "V"  PC
 SG_ S2P_Lmt17_Under_UModule4_33 : 48|16@1+ (0.1,0) [0|6553.5] "V"  PC

BO_ 2418208354 S2P_Lmt17__34: 8 SBMU
 SG_ S2P_Lmt17_Over_UModule3_34 : 0|16@1+ (0.1,0) [0|6553.5] "V"  PC
 SG_ S2P_Lmt17_Under_UModule3_34 : 16|16@1+ (0.1,0) [0|6553.5] "V"  PC
 SG_ S2P_Lmt17_Over_UModule4_34 : 32|16@1+ (0.1,0) [0|6553.5] "V"  PC
 SG_ S2P_Lmt17_Under_UModule4_34 : 48|16@1+ (0.1,0) [0|6553.5] "V"  PC

BO_ 2418208355 S2P_Lmt17__35: 8 SBMU
 SG_ S2P_Lmt17_Over_UModule3_35 : 0|16@1+ (0.1,0) [0|6553.5] "V"  PC
 SG_ S2P_Lmt17_Under_UModule3_35 : 16|16@1+ (0.1,0) [0|6553.5] "V"  PC
 SG_ S2P_Lmt17_Over_UModule4_35 : 32|16@1+ (0.1,0) [0|6553.5] "V"  PC
 SG_ S2P_Lmt17_Under_UModule4_35 : 48|16@1+ (0.1,0) [0|6553.5] "V"  PC

BO_ 2418208356 S2P_Lmt17__36: 8 SBMU
 SG_ S2P_Lmt17_Over_UModule3_36 : 0|16@1+ (0.1,0) [0|6553.5] "V"  PC
 SG_ S2P_Lmt17_Under_UModule3_36 : 16|16@1+ (0.1,0) [0|6553.5] "V"  PC
 SG_ S2P_Lmt17_Over_UModule4_36 : 32|16@1+ (0.1,0) [0|6553.5] "V"  PC
 SG_ S2P_Lmt17_Under_UModule4_36 : 48|16@1+ (0.1,0) [0|6553.5] "V"  PC

BO_ 2418208357 S2P_Lmt17__37: 8 SBMU
 SG_ S2P_Lmt17_Over_UModule3_37 : 0|16@1+ (0.1,0) [0|6553.5] "V"  PC
 SG_ S2P_Lmt17_Under_UModule3_37 : 16|16@1+ (0.1,0) [0|6553.5] "V"  PC
 SG_ S2P_Lmt17_Over_UModule4_37 : 32|16@1+ (0.1,0) [0|6553.5] "V"  PC
 SG_ S2P_Lmt17_Under_UModule4_37 : 48|16@1+ (0.1,0) [0|6553.5] "V"  PC

BO_ 2418208358 S2P_Lmt17__38: 8 SBMU
 SG_ S2P_Lmt17_Over_UModule3_38 : 0|16@1+ (0.1,0) [0|6553.5] "V"  PC
 SG_ S2P_Lmt17_Under_UModule3_38 : 16|16@1+ (0.1,0) [0|6553.5] "V"  PC
 SG_ S2P_Lmt17_Over_UModule4_38 : 32|16@1+ (0.1,0) [0|6553.5] "V"  PC
 SG_ S2P_Lmt17_Under_UModule4_38 : 48|16@1+ (0.1,0) [0|6553.5] "V"  PC

BO_ 2418208359 S2P_Lmt17__39: 8 SBMU
 SG_ S2P_Lmt17_Over_UModule3_39 : 0|16@1+ (0.1,0) [0|6553.5] "V"  PC
 SG_ S2P_Lmt17_Under_UModule3_39 : 16|16@1+ (0.1,0) [0|6553.5] "V"  PC
 SG_ S2P_Lmt17_Over_UModule4_39 : 32|16@1+ (0.1,0) [0|6553.5] "V"  PC
 SG_ S2P_Lmt17_Under_UModule4_39 : 48|16@1+ (0.1,0) [0|6553.5] "V"  PC

BO_ 2418208360 S2P_Lmt17__40: 8 SBMU
 SG_ S2P_Lmt17_Over_UModule3_40 : 0|16@1+ (0.1,0) [0|6553.5] "V"  PC
 SG_ S2P_Lmt17_Under_UModule3_40 : 16|16@1+ (0.1,0) [0|6553.5] "V"  PC
 SG_ S2P_Lmt17_Over_UModule4_40 : 32|16@1+ (0.1,0) [0|6553.5] "V"  PC
 SG_ S2P_Lmt17_Under_UModule4_40 : 48|16@1+ (0.1,0) [0|6553.5] "V"  PC

BO_ 2418208361 S2P_Lmt17__41: 8 SBMU
 SG_ S2P_Lmt17_Over_UModule3_41 : 0|16@1+ (0.1,0) [0|6553.5] "V"  PC
 SG_ S2P_Lmt17_Under_UModule3_41 : 16|16@1+ (0.1,0) [0|6553.5] "V"  PC
 SG_ S2P_Lmt17_Over_UModule4_41 : 32|16@1+ (0.1,0) [0|6553.5] "V"  PC
 SG_ S2P_Lmt17_Under_UModule4_41 : 48|16@1+ (0.1,0) [0|6553.5] "V"  PC

BO_ 2418208362 S2P_Lmt17__42: 8 SBMU
 SG_ S2P_Lmt17_Over_UModule3_42 : 0|16@1+ (0.1,0) [0|6553.5] "V"  PC
 SG_ S2P_Lmt17_Under_UModule3_42 : 16|16@1+ (0.1,0) [0|6553.5] "V"  PC
 SG_ S2P_Lmt17_Over_UModule4_42 : 32|16@1+ (0.1,0) [0|6553.5] "V"  PC
 SG_ S2P_Lmt17_Under_UModule4_42 : 48|16@1+ (0.1,0) [0|6553.5] "V"  PC

BO_ 2418208363 S2P_Lmt17__43: 8 SBMU
 SG_ S2P_Lmt17_Over_UModule3_43 : 0|16@1+ (0.1,0) [0|6553.5] "V"  PC
 SG_ S2P_Lmt17_Under_UModule3_43 : 16|16@1+ (0.1,0) [0|6553.5] "V"  PC
 SG_ S2P_Lmt17_Over_UModule4_43 : 32|16@1+ (0.1,0) [0|6553.5] "V"  PC
 SG_ S2P_Lmt17_Under_UModule4_43 : 48|16@1+ (0.1,0) [0|6553.5] "V"  PC

BO_ 2418208364 S2P_Lmt17__44: 8 SBMU
 SG_ S2P_Lmt17_Over_UModule3_44 : 0|16@1+ (0.1,0) [0|6553.5] "V"  PC
 SG_ S2P_Lmt17_Under_UModule3_44 : 16|16@1+ (0.1,0) [0|6553.5] "V"  PC
 SG_ S2P_Lmt17_Over_UModule4_44 : 32|16@1+ (0.1,0) [0|6553.5] "V"  PC
 SG_ S2P_Lmt17_Under_UModule4_44 : 48|16@1+ (0.1,0) [0|6553.5] "V"  PC

BO_ 2418208365 S2P_Lmt17__45: 8 SBMU
 SG_ S2P_Lmt17_Over_UModule3_45 : 0|16@1+ (0.1,0) [0|6553.5] "V"  PC
 SG_ S2P_Lmt17_Under_UModule3_45 : 16|16@1+ (0.1,0) [0|6553.5] "V"  PC
 SG_ S2P_Lmt17_Over_UModule4_45 : 32|16@1+ (0.1,0) [0|6553.5] "V"  PC
 SG_ S2P_Lmt17_Under_UModule4_45 : 48|16@1+ (0.1,0) [0|6553.5] "V"  PC

BO_ 2418208366 S2P_Lmt17__46: 8 SBMU
 SG_ S2P_Lmt17_Over_UModule3_46 : 0|16@1+ (0.1,0) [0|6553.5] "V"  PC
 SG_ S2P_Lmt17_Under_UModule3_46 : 16|16@1+ (0.1,0) [0|6553.5] "V"  PC
 SG_ S2P_Lmt17_Over_UModule4_46 : 32|16@1+ (0.1,0) [0|6553.5] "V"  PC
 SG_ S2P_Lmt17_Under_UModule4_46 : 48|16@1+ (0.1,0) [0|6553.5] "V"  PC

BO_ 2418208367 S2P_Lmt17__47: 8 SBMU
 SG_ S2P_Lmt17_Over_UModule3_47 : 0|16@1+ (0.1,0) [0|6553.5] "V"  PC
 SG_ S2P_Lmt17_Under_UModule3_47 : 16|16@1+ (0.1,0) [0|6553.5] "V"  PC
 SG_ S2P_Lmt17_Over_UModule4_47 : 32|16@1+ (0.1,0) [0|6553.5] "V"  PC
 SG_ S2P_Lmt17_Under_UModule4_47 : 48|16@1+ (0.1,0) [0|6553.5] "V"  PC

BO_ 2418208368 S2P_Lmt17__48: 8 SBMU
 SG_ S2P_Lmt17_Over_UModule3_48 : 0|16@1+ (0.1,0) [0|6553.5] "V"  PC
 SG_ S2P_Lmt17_Under_UModule3_48 : 16|16@1+ (0.1,0) [0|6553.5] "V"  PC
 SG_ S2P_Lmt17_Over_UModule4_48 : 32|16@1+ (0.1,0) [0|6553.5] "V"  PC
 SG_ S2P_Lmt17_Under_UModule4_48 : 48|16@1+ (0.1,0) [0|6553.5] "V"  PC

BO_ 2418208369 S2P_Lmt17__49: 8 SBMU
 SG_ S2P_Lmt17_Over_UModule3_49 : 0|16@1+ (0.1,0) [0|6553.5] "V"  PC
 SG_ S2P_Lmt17_Under_UModule3_49 : 16|16@1+ (0.1,0) [0|6553.5] "V"  PC
 SG_ S2P_Lmt17_Over_UModule4_49 : 32|16@1+ (0.1,0) [0|6553.5] "V"  PC
 SG_ S2P_Lmt17_Under_UModule4_49 : 48|16@1+ (0.1,0) [0|6553.5] "V"  PC

BO_ 2418208370 S2P_Lmt17__50: 8 SBMU
 SG_ S2P_Lmt17_Over_UModule3_50 : 0|16@1+ (0.1,0) [0|6553.5] "V"  PC
 SG_ S2P_Lmt17_Under_UModule3_50 : 16|16@1+ (0.1,0) [0|6553.5] "V"  PC
 SG_ S2P_Lmt17_Over_UModule4_50 : 32|16@1+ (0.1,0) [0|6553.5] "V"  PC
 SG_ S2P_Lmt17_Under_UModule4_50 : 48|16@1+ (0.1,0) [0|6553.5] "V"  PC

BO_ 2418208371 S2P_Lmt17__51: 8 SBMU
 SG_ S2P_Lmt17_Over_UModule3_51 : 0|16@1+ (0.1,0) [0|6553.5] "V"  PC
 SG_ S2P_Lmt17_Under_UModule3_51 : 16|16@1+ (0.1,0) [0|6553.5] "V"  PC
 SG_ S2P_Lmt17_Over_UModule4_51 : 32|16@1+ (0.1,0) [0|6553.5] "V"  PC
 SG_ S2P_Lmt17_Under_UModule4_51 : 48|16@1+ (0.1,0) [0|6553.5] "V"  PC

BO_ 2418208372 S2P_Lmt17__52: 8 SBMU
 SG_ S2P_Lmt17_Over_UModule3_52 : 0|16@1+ (0.1,0) [0|6553.5] "V"  PC
 SG_ S2P_Lmt17_Under_UModule3_52 : 16|16@1+ (0.1,0) [0|6553.5] "V"  PC
 SG_ S2P_Lmt17_Over_UModule4_52 : 32|16@1+ (0.1,0) [0|6553.5] "V"  PC
 SG_ S2P_Lmt17_Under_UModule4_52 : 48|16@1+ (0.1,0) [0|6553.5] "V"  PC

BO_ 2418208373 S2P_Lmt17__53: 8 SBMU
 SG_ S2P_Lmt17_Over_UModule3_53 : 0|16@1+ (0.1,0) [0|6553.5] "V"  PC
 SG_ S2P_Lmt17_Under_UModule3_53 : 16|16@1+ (0.1,0) [0|6553.5] "V"  PC
 SG_ S2P_Lmt17_Over_UModule4_53 : 32|16@1+ (0.1,0) [0|6553.5] "V"  PC
 SG_ S2P_Lmt17_Under_UModule4_53 : 48|16@1+ (0.1,0) [0|6553.5] "V"  PC

BO_ 2418208374 S2P_Lmt17__54: 8 SBMU
 SG_ S2P_Lmt17_Over_UModule3_54 : 0|16@1+ (0.1,0) [0|6553.5] "V"  PC
 SG_ S2P_Lmt17_Under_UModule3_54 : 16|16@1+ (0.1,0) [0|6553.5] "V"  PC
 SG_ S2P_Lmt17_Over_UModule4_54 : 32|16@1+ (0.1,0) [0|6553.5] "V"  PC
 SG_ S2P_Lmt17_Under_UModule4_54 : 48|16@1+ (0.1,0) [0|6553.5] "V"  PC

BO_ 2418208375 S2P_Lmt17__55: 8 SBMU
 SG_ S2P_Lmt17_Over_UModule3_55 : 0|16@1+ (0.1,0) [0|6553.5] "V"  PC
 SG_ S2P_Lmt17_Under_UModule3_55 : 16|16@1+ (0.1,0) [0|6553.5] "V"  PC
 SG_ S2P_Lmt17_Over_UModule4_55 : 32|16@1+ (0.1,0) [0|6553.5] "V"  PC
 SG_ S2P_Lmt17_Under_UModule4_55 : 48|16@1+ (0.1,0) [0|6553.5] "V"  PC

BO_ 2418208376 S2P_Lmt17__56: 8 SBMU
 SG_ S2P_Lmt17_Over_UModule3_56 : 0|16@1+ (0.1,0) [0|6553.5] "V"  PC
 SG_ S2P_Lmt17_Under_UModule3_56 : 16|16@1+ (0.1,0) [0|6553.5] "V"  PC
 SG_ S2P_Lmt17_Over_UModule4_56 : 32|16@1+ (0.1,0) [0|6553.5] "V"  PC
 SG_ S2P_Lmt17_Under_UModule4_56 : 48|16@1+ (0.1,0) [0|6553.5] "V"  PC

BO_ 2418208377 S2P_Lmt17__57: 8 SBMU
 SG_ S2P_Lmt17_Over_UModule3_57 : 0|16@1+ (0.1,0) [0|6553.5] "V"  PC
 SG_ S2P_Lmt17_Under_UModule3_57 : 16|16@1+ (0.1,0) [0|6553.5] "V"  PC
 SG_ S2P_Lmt17_Over_UModule4_57 : 32|16@1+ (0.1,0) [0|6553.5] "V"  PC
 SG_ S2P_Lmt17_Under_UModule4_57 : 48|16@1+ (0.1,0) [0|6553.5] "V"  PC

BO_ 2418208378 S2P_Lmt17__58: 8 SBMU
 SG_ S2P_Lmt17_Over_UModule3_58 : 0|16@1+ (0.1,0) [0|6553.5] "V"  PC
 SG_ S2P_Lmt17_Under_UModule3_58 : 16|16@1+ (0.1,0) [0|6553.5] "V"  PC
 SG_ S2P_Lmt17_Over_UModule4_58 : 32|16@1+ (0.1,0) [0|6553.5] "V"  PC
 SG_ S2P_Lmt17_Under_UModule4_58 : 48|16@1+ (0.1,0) [0|6553.5] "V"  PC

BO_ 2418208379 S2P_Lmt17__59: 8 SBMU
 SG_ S2P_Lmt17_Over_UModule3_59 : 0|16@1+ (0.1,0) [0|6553.5] "V"  PC
 SG_ S2P_Lmt17_Under_UModule3_59 : 16|16@1+ (0.1,0) [0|6553.5] "V"  PC
 SG_ S2P_Lmt17_Over_UModule4_59 : 32|16@1+ (0.1,0) [0|6553.5] "V"  PC
 SG_ S2P_Lmt17_Under_UModule4_59 : 48|16@1+ (0.1,0) [0|6553.5] "V"  PC

BO_ 2418208380 S2P_Lmt17__60: 8 SBMU
 SG_ S2P_Lmt17_Over_UModule3_60 : 0|16@1+ (0.1,0) [0|6553.5] "V"  PC
 SG_ S2P_Lmt17_Under_UModule3_60 : 16|16@1+ (0.1,0) [0|6553.5] "V"  PC
 SG_ S2P_Lmt17_Over_UModule4_60 : 32|16@1+ (0.1,0) [0|6553.5] "V"  PC
 SG_ S2P_Lmt17_Under_UModule4_60 : 48|16@1+ (0.1,0) [0|6553.5] "V"  PC

BO_ 2418208381 S2P_Lmt17__61: 8 SBMU
 SG_ S2P_Lmt17_Over_UModule3_61 : 0|16@1+ (0.1,0) [0|6553.5] "V"  PC
 SG_ S2P_Lmt17_Under_UModule3_61 : 16|16@1+ (0.1,0) [0|6553.5] "V"  PC
 SG_ S2P_Lmt17_Over_UModule4_61 : 32|16@1+ (0.1,0) [0|6553.5] "V"  PC
 SG_ S2P_Lmt17_Under_UModule4_61 : 48|16@1+ (0.1,0) [0|6553.5] "V"  PC

BO_ 2418208382 S2P_Lmt17__62: 8 SBMU
 SG_ S2P_Lmt17_Over_UModule3_62 : 0|16@1+ (0.1,0) [0|6553.5] "V"  PC
 SG_ S2P_Lmt17_Under_UModule3_62 : 16|16@1+ (0.1,0) [0|6553.5] "V"  PC
 SG_ S2P_Lmt17_Over_UModule4_62 : 32|16@1+ (0.1,0) [0|6553.5] "V"  PC
 SG_ S2P_Lmt17_Under_UModule4_62 : 48|16@1+ (0.1,0) [0|6553.5] "V"  PC

BO_ 2418208383 S2P_Lmt17__63: 8 SBMU
 SG_ S2P_Lmt17_Over_UModule3_63 : 0|16@1+ (0.1,0) [0|6553.5] "V"  PC
 SG_ S2P_Lmt17_Under_UModule3_63 : 16|16@1+ (0.1,0) [0|6553.5] "V"  PC
 SG_ S2P_Lmt17_Over_UModule4_63 : 32|16@1+ (0.1,0) [0|6553.5] "V"  PC
 SG_ S2P_Lmt17_Under_UModule4_63 : 48|16@1+ (0.1,0) [0|6553.5] "V"  PC

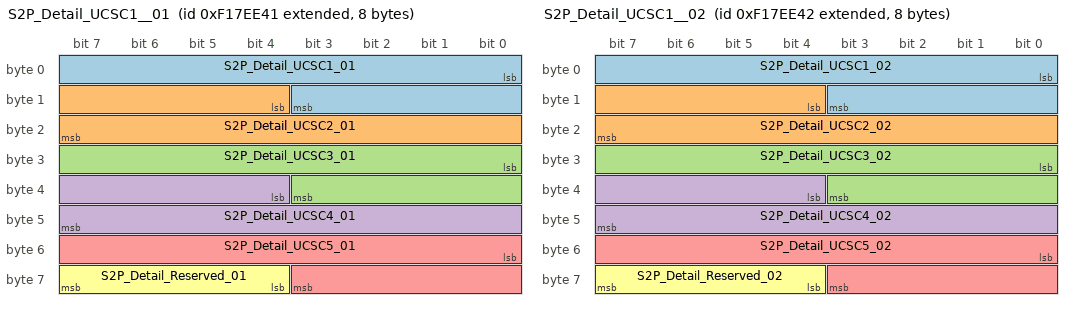
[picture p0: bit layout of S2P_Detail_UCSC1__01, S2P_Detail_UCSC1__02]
BO_ 2400710209 S2P_Detail_UCSC1__01: 8 SBMU
 SG_ S2P_Detail_UCSC1_01 : 0|12@1+ (0.1,0) [0|409.5] "V"  PC
 SG_ S2P_Detail_UCSC2_01 : 12|12@1+ (0.1,0) [0|409.5] "V"  PC
 SG_ S2P_Detail_UCSC3_01 : 24|12@1+ (0.1,0) [0|409.5] "V"  PC
 SG_ S2P_Detail_UCSC4_01 : 36|12@1+ (0.1,0) [0|409.5] "V"  PC
 SG_ S2P_Detail_UCSC5_01 : 48|12@1+ (0.1,0) [0|409.5] "V"  PC
 SG_ S2P_Detail_Reserved_01 : 60|4@1+ (1,0) [0|15] ""  PC

BO_ 2400710210 S2P_Detail_UCSC1__02: 8 SBMU
 SG_ S2P_Detail_UCSC1_02 : 0|12@1+ (0.1,0) [0|409.5] "V"  PC
 SG_ S2P_Detail_UCSC2_02 : 12|12@1+ (0.1,0) [0|409.5] "V"  PC
 SG_ S2P_Detail_UCSC3_02 : 24|12@1+ (0.1,0) [0|409.5] "V"  PC
 SG_ S2P_Detail_UCSC4_02 : 36|12@1+ (0.1,0) [0|409.5] "V"  PC
 SG_ S2P_Detail_UCSC5_02 : 48|12@1+ (0.1,0) [0|409.5] "V"  PC
 SG_ S2P_Detail_Reserved_02 : 60|4@1+ (1,0) [0|15] ""  PC

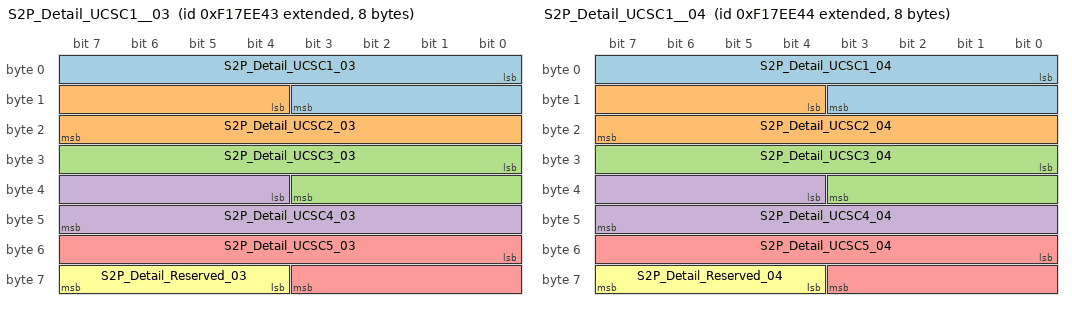
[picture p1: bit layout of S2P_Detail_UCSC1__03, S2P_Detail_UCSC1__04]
BO_ 2400710211 S2P_Detail_UCSC1__03: 8 SBMU
 SG_ S2P_Detail_UCSC1_03 : 0|12@1+ (0.1,0) [0|409.5] "V"  PC
 SG_ S2P_Detail_UCSC2_03 : 12|12@1+ (0.1,0) [0|409.5] "V"  PC
 SG_ S2P_Detail_UCSC3_03 : 24|12@1+ (0.1,0) [0|409.5] "V"  PC
 SG_ S2P_Detail_UCSC4_03 : 36|12@1+ (0.1,0) [0|409.5] "V"  PC
 SG_ S2P_Detail_UCSC5_03 : 48|12@1+ (0.1,0) [0|409.5] "V"  PC
 SG_ S2P_Detail_Reserved_03 : 60|4@1+ (1,0) [0|15] ""  PC

BO_ 2400710212 S2P_Detail_UCSC1__04: 8 SBMU
 SG_ S2P_Detail_UCSC1_04 : 0|12@1+ (0.1,0) [0|409.5] "V"  PC
 SG_ S2P_Detail_UCSC2_04 : 12|12@1+ (0.1,0) [0|409.5] "V"  PC
 SG_ S2P_Detail_UCSC3_04 : 24|12@1+ (0.1,0) [0|409.5] "V"  PC
 SG_ S2P_Detail_UCSC4_04 : 36|12@1+ (0.1,0) [0|409.5] "V"  PC
 SG_ S2P_Detail_UCSC5_04 : 48|12@1+ (0.1,0) [0|409.5] "V"  PC
 SG_ S2P_Detail_Reserved_04 : 60|4@1+ (1,0) [0|15] ""  PC

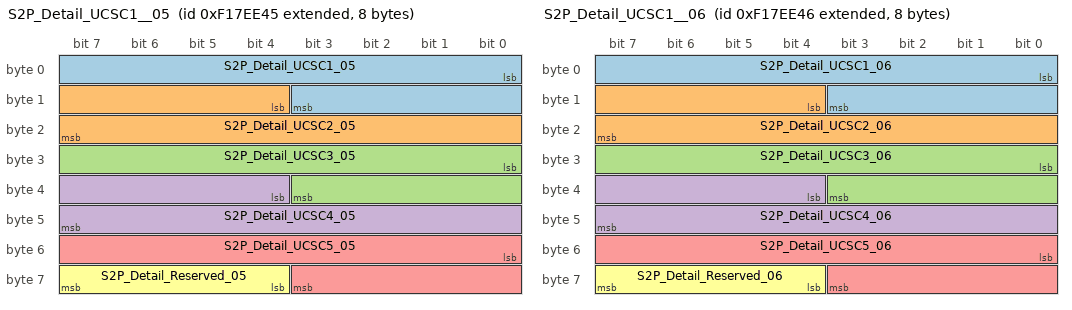
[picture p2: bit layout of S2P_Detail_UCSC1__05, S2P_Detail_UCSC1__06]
BO_ 2400710213 S2P_Detail_UCSC1__05: 8 SBMU
 SG_ S2P_Detail_UCSC1_05 : 0|12@1+ (0.1,0) [0|409.5] "V"  PC
 SG_ S2P_Detail_UCSC2_05 : 12|12@1+ (0.1,0) [0|409.5] "V"  PC
 SG_ S2P_Detail_UCSC3_05 : 24|12@1+ (0.1,0) [0|409.5] "V"  PC
 SG_ S2P_Detail_UCSC4_05 : 36|12@1+ (0.1,0) [0|409.5] "V"  PC
 SG_ S2P_Detail_UCSC5_05 : 48|12@1+ (0.1,0) [0|409.5] "V"  PC
 SG_ S2P_Detail_Reserved_05 : 60|4@1+ (1,0) [0|15] ""  PC

BO_ 2400710214 S2P_Detail_UCSC1__06: 8 SBMU
 SG_ S2P_Detail_UCSC1_06 : 0|12@1+ (0.1,0) [0|409.5] "V"  PC
 SG_ S2P_Detail_UCSC2_06 : 12|12@1+ (0.1,0) [0|409.5] "V"  PC
 SG_ S2P_Detail_UCSC3_06 : 24|12@1+ (0.1,0) [0|409.5] "V"  PC
 SG_ S2P_Detail_UCSC4_06 : 36|12@1+ (0.1,0) [0|409.5] "V"  PC
 SG_ S2P_Detail_UCSC5_06 : 48|12@1+ (0.1,0) [0|409.5] "V"  PC
 SG_ S2P_Detail_Reserved_06 : 60|4@1+ (1,0) [0|15] ""  PC

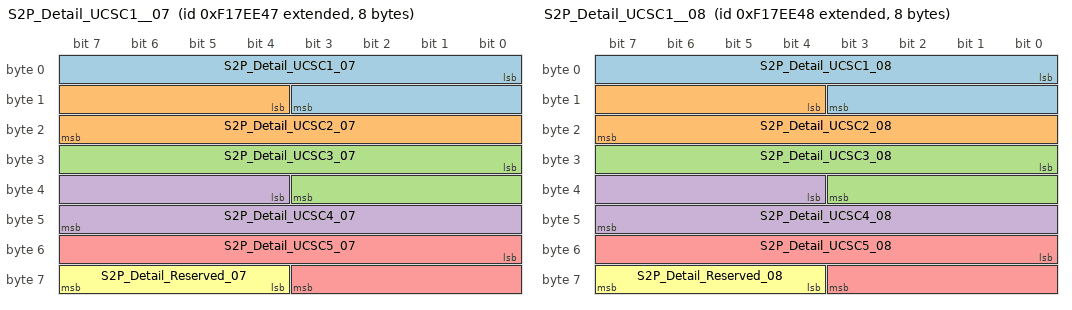
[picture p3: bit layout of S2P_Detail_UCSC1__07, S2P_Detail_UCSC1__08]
BO_ 2400710215 S2P_Detail_UCSC1__07: 8 SBMU
 SG_ S2P_Detail_UCSC1_07 : 0|12@1+ (0.1,0) [0|409.5] "V"  PC
 SG_ S2P_Detail_UCSC2_07 : 12|12@1+ (0.1,0) [0|409.5] "V"  PC
 SG_ S2P_Detail_UCSC3_07 : 24|12@1+ (0.1,0) [0|409.5] "V"  PC
 SG_ S2P_Detail_UCSC4_07 : 36|12@1+ (0.1,0) [0|409.5] "V"  PC
 SG_ S2P_Detail_UCSC5_07 : 48|12@1+ (0.1,0) [0|409.5] "V"  PC
 SG_ S2P_Detail_Reserved_07 : 60|4@1+ (1,0) [0|15] ""  PC

BO_ 2400710216 S2P_Detail_UCSC1__08: 8 SBMU
 SG_ S2P_Detail_UCSC1_08 : 0|12@1+ (0.1,0) [0|409.5] "V"  PC
 SG_ S2P_Detail_UCSC2_08 : 12|12@1+ (0.1,0) [0|409.5] "V"  PC
 SG_ S2P_Detail_UCSC3_08 : 24|12@1+ (0.1,0) [0|409.5] "V"  PC
 SG_ S2P_Detail_UCSC4_08 : 36|12@1+ (0.1,0) [0|409.5] "V"  PC
 SG_ S2P_Detail_UCSC5_08 : 48|12@1+ (0.1,0) [0|409.5] "V"  PC
 SG_ S2P_Detail_Reserved_08 : 60|4@1+ (1,0) [0|15] ""  PC

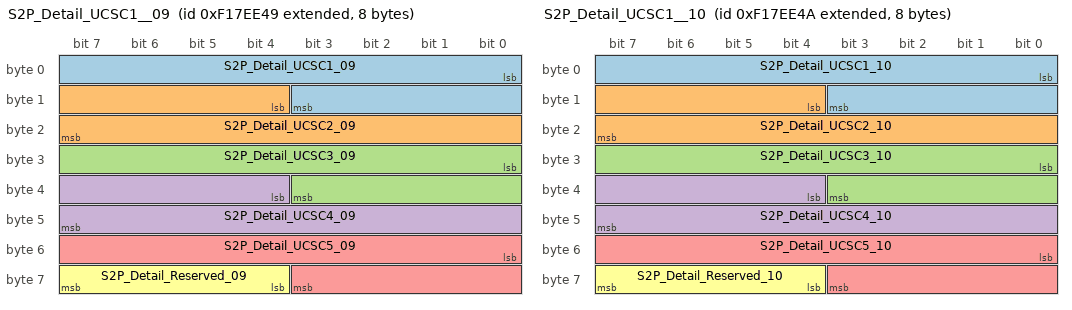
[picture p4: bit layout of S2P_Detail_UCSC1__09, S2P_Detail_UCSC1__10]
BO_ 2400710217 S2P_Detail_UCSC1__09: 8 SBMU
 SG_ S2P_Detail_UCSC1_09 : 0|12@1+ (0.1,0) [0|409.5] "V"  PC
 SG_ S2P_Detail_UCSC2_09 : 12|12@1+ (0.1,0) [0|409.5] "V"  PC
 SG_ S2P_Detail_UCSC3_09 : 24|12@1+ (0.1,0) [0|409.5] "V"  PC
 SG_ S2P_Detail_UCSC4_09 : 36|12@1+ (0.1,0) [0|409.5] "V"  PC
 SG_ S2P_Detail_UCSC5_09 : 48|12@1+ (0.1,0) [0|409.5] "V"  PC
 SG_ S2P_Detail_Reserved_09 : 60|4@1+ (1,0) [0|15] ""  PC

BO_ 2400710218 S2P_Detail_UCSC1__10: 8 SBMU
 SG_ S2P_Detail_UCSC1_10 : 0|12@1+ (0.1,0) [0|409.5] "V"  PC
 SG_ S2P_Detail_UCSC2_10 : 12|12@1+ (0.1,0) [0|409.5] "V"  PC
 SG_ S2P_Detail_UCSC3_10 : 24|12@1+ (0.1,0) [0|409.5] "V"  PC
 SG_ S2P_Detail_UCSC4_10 : 36|12@1+ (0.1,0) [0|409.5] "V"  PC
 SG_ S2P_Detail_UCSC5_10 : 48|12@1+ (0.1,0) [0|409.5] "V"  PC
 SG_ S2P_Detail_Reserved_10 : 60|4@1+ (1,0) [0|15] ""  PC

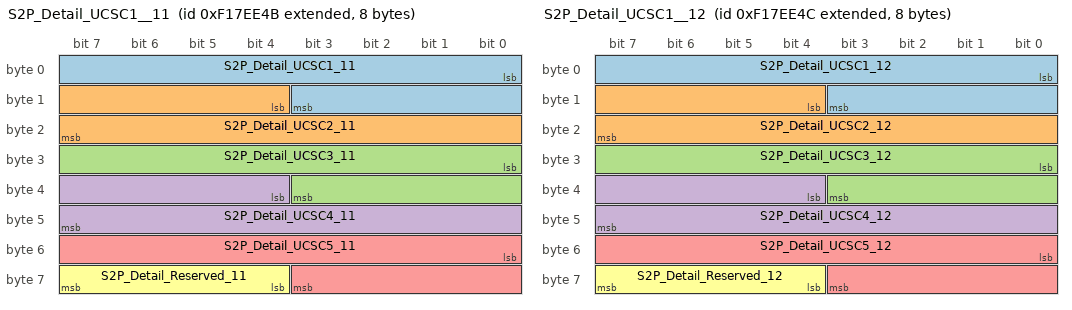
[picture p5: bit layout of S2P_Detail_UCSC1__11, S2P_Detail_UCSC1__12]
BO_ 2400710219 S2P_Detail_UCSC1__11: 8 SBMU
 SG_ S2P_Detail_UCSC1_11 : 0|12@1+ (0.1,0) [0|409.5] "V"  PC
 SG_ S2P_Detail_UCSC2_11 : 12|12@1+ (0.1,0) [0|409.5] "V"  PC
 SG_ S2P_Detail_UCSC3_11 : 24|12@1+ (0.1,0) [0|409.5] "V"  PC
 SG_ S2P_Detail_UCSC4_11 : 36|12@1+ (0.1,0) [0|409.5] "V"  PC
 SG_ S2P_Detail_UCSC5_11 : 48|12@1+ (0.1,0) [0|409.5] "V"  PC
 SG_ S2P_Detail_Reserved_11 : 60|4@1+ (1,0) [0|15] ""  PC

BO_ 2400710220 S2P_Detail_UCSC1__12: 8 SBMU
 SG_ S2P_Detail_UCSC1_12 : 0|12@1+ (0.1,0) [0|409.5] "V"  PC
 SG_ S2P_Detail_UCSC2_12 : 12|12@1+ (0.1,0) [0|409.5] "V"  PC
 SG_ S2P_Detail_UCSC3_12 : 24|12@1+ (0.1,0) [0|409.5] "V"  PC
 SG_ S2P_Detail_UCSC4_12 : 36|12@1+ (0.1,0) [0|409.5] "V"  PC
 SG_ S2P_Detail_UCSC5_12 : 48|12@1+ (0.1,0) [0|409.5] "V"  PC
 SG_ S2P_Detail_Reserved_12 : 60|4@1+ (1,0) [0|15] ""  PC

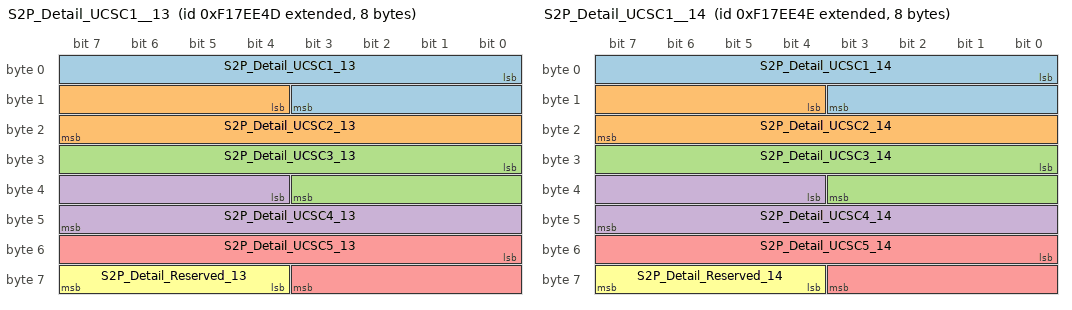
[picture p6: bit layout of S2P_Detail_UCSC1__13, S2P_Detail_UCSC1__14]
BO_ 2400710221 S2P_Detail_UCSC1__13: 8 SBMU
 SG_ S2P_Detail_UCSC1_13 : 0|12@1+ (0.1,0) [0|409.5] "V"  PC
 SG_ S2P_Detail_UCSC2_13 : 12|12@1+ (0.1,0) [0|409.5] "V"  PC
 SG_ S2P_Detail_UCSC3_13 : 24|12@1+ (0.1,0) [0|409.5] "V"  PC
 SG_ S2P_Detail_UCSC4_13 : 36|12@1+ (0.1,0) [0|409.5] "V"  PC
 SG_ S2P_Detail_UCSC5_13 : 48|12@1+ (0.1,0) [0|409.5] "V"  PC
 SG_ S2P_Detail_Reserved_13 : 60|4@1+ (1,0) [0|15] ""  PC

BO_ 2400710222 S2P_Detail_UCSC1__14: 8 SBMU
 SG_ S2P_Detail_UCSC1_14 : 0|12@1+ (0.1,0) [0|409.5] "V"  PC
 SG_ S2P_Detail_UCSC2_14 : 12|12@1+ (0.1,0) [0|409.5] "V"  PC
 SG_ S2P_Detail_UCSC3_14 : 24|12@1+ (0.1,0) [0|409.5] "V"  PC
 SG_ S2P_Detail_UCSC4_14 : 36|12@1+ (0.1,0) [0|409.5] "V"  PC
 SG_ S2P_Detail_UCSC5_14 : 48|12@1+ (0.1,0) [0|409.5] "V"  PC
 SG_ S2P_Detail_Reserved_14 : 60|4@1+ (1,0) [0|15] ""  PC

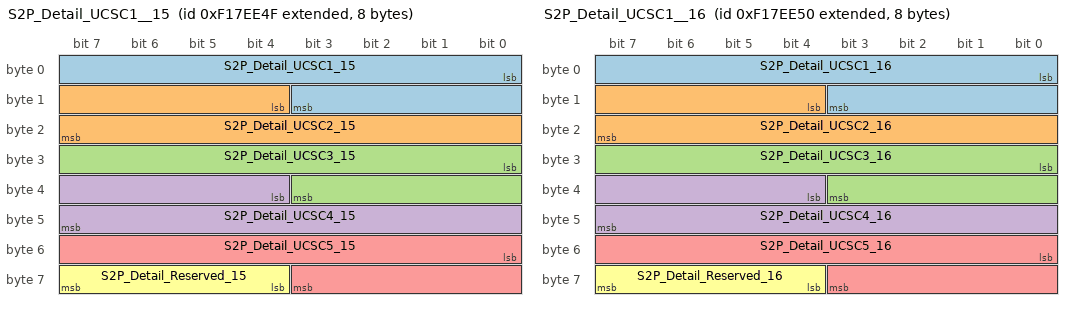
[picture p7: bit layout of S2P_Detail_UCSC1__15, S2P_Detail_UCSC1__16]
BO_ 2400710223 S2P_Detail_UCSC1__15: 8 SBMU
 SG_ S2P_Detail_UCSC1_15 : 0|12@1+ (0.1,0) [0|409.5] "V"  PC
 SG_ S2P_Detail_UCSC2_15 : 12|12@1+ (0.1,0) [0|409.5] "V"  PC
 SG_ S2P_Detail_UCSC3_15 : 24|12@1+ (0.1,0) [0|409.5] "V"  PC
 SG_ S2P_Detail_UCSC4_15 : 36|12@1+ (0.1,0) [0|409.5] "V"  PC
 SG_ S2P_Detail_UCSC5_15 : 48|12@1+ (0.1,0) [0|409.5] "V"  PC
 SG_ S2P_Detail_Reserved_15 : 60|4@1+ (1,0) [0|15] ""  PC

BO_ 2400710224 S2P_Detail_UCSC1__16: 8 SBMU
 SG_ S2P_Detail_UCSC1_16 : 0|12@1+ (0.1,0) [0|409.5] "V"  PC
 SG_ S2P_Detail_UCSC2_16 : 12|12@1+ (0.1,0) [0|409.5] "V"  PC
 SG_ S2P_Detail_UCSC3_16 : 24|12@1+ (0.1,0) [0|409.5] "V"  PC
 SG_ S2P_Detail_UCSC4_16 : 36|12@1+ (0.1,0) [0|409.5] "V"  PC
 SG_ S2P_Detail_UCSC5_16 : 48|12@1+ (0.1,0) [0|409.5] "V"  PC
 SG_ S2P_Detail_Reserved_16 : 60|4@1+ (1,0) [0|15] ""  PC

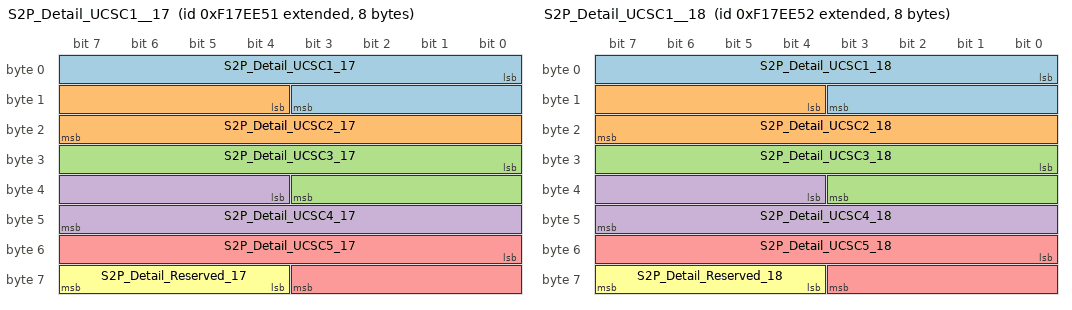
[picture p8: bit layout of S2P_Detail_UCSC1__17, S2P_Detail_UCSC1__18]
BO_ 2400710225 S2P_Detail_UCSC1__17: 8 SBMU
 SG_ S2P_Detail_UCSC1_17 : 0|12@1+ (0.1,0) [0|409.5] "V"  PC
 SG_ S2P_Detail_UCSC2_17 : 12|12@1+ (0.1,0) [0|409.5] "V"  PC
 SG_ S2P_Detail_UCSC3_17 : 24|12@1+ (0.1,0) [0|409.5] "V"  PC
 SG_ S2P_Detail_UCSC4_17 : 36|12@1+ (0.1,0) [0|409.5] "V"  PC
 SG_ S2P_Detail_UCSC5_17 : 48|12@1+ (0.1,0) [0|409.5] "V"  PC
 SG_ S2P_Detail_Reserved_17 : 60|4@1+ (1,0) [0|15] ""  PC

BO_ 2400710226 S2P_Detail_UCSC1__18: 8 SBMU
 SG_ S2P_Detail_UCSC1_18 : 0|12@1+ (0.1,0) [0|409.5] "V"  PC
 SG_ S2P_Detail_UCSC2_18 : 12|12@1+ (0.1,0) [0|409.5] "V"  PC
 SG_ S2P_Detail_UCSC3_18 : 24|12@1+ (0.1,0) [0|409.5] "V"  PC
 SG_ S2P_Detail_UCSC4_18 : 36|12@1+ (0.1,0) [0|409.5] "V"  PC
 SG_ S2P_Detail_UCSC5_18 : 48|12@1+ (0.1,0) [0|409.5] "V"  PC
 SG_ S2P_Detail_Reserved_18 : 60|4@1+ (1,0) [0|15] ""  PC

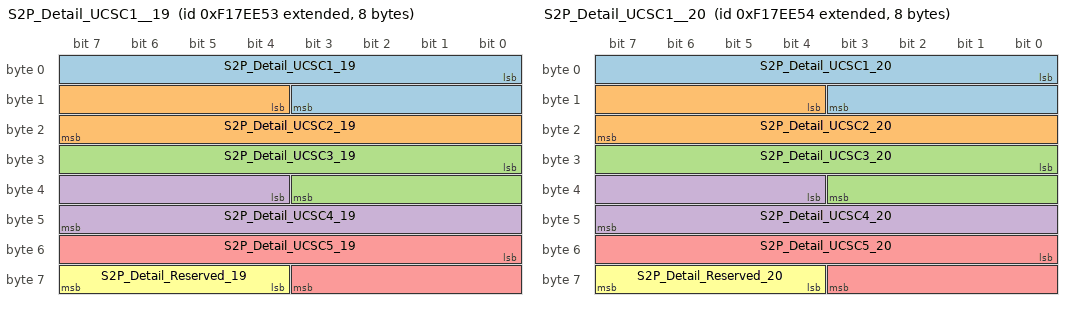
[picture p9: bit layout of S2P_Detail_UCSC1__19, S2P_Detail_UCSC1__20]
BO_ 2400710227 S2P_Detail_UCSC1__19: 8 SBMU
 SG_ S2P_Detail_UCSC1_19 : 0|12@1+ (0.1,0) [0|409.5] "V"  PC
 SG_ S2P_Detail_UCSC2_19 : 12|12@1+ (0.1,0) [0|409.5] "V"  PC
 SG_ S2P_Detail_UCSC3_19 : 24|12@1+ (0.1,0) [0|409.5] "V"  PC
 SG_ S2P_Detail_UCSC4_19 : 36|12@1+ (0.1,0) [0|409.5] "V"  PC
 SG_ S2P_Detail_UCSC5_19 : 48|12@1+ (0.1,0) [0|409.5] "V"  PC
 SG_ S2P_Detail_Reserved_19 : 60|4@1+ (1,0) [0|15] ""  PC

BO_ 2400710228 S2P_Detail_UCSC1__20: 8 SBMU
 SG_ S2P_Detail_UCSC1_20 : 0|12@1+ (0.1,0) [0|409.5] "V"  PC
 SG_ S2P_Detail_UCSC2_20 : 12|12@1+ (0.1,0) [0|409.5] "V"  PC
 SG_ S2P_Detail_UCSC3_20 : 24|12@1+ (0.1,0) [0|409.5] "V"  PC
 SG_ S2P_Detail_UCSC4_20 : 36|12@1+ (0.1,0) [0|409.5] "V"  PC
 SG_ S2P_Detail_UCSC5_20 : 48|12@1+ (0.1,0) [0|409.5] "V"  PC
 SG_ S2P_Detail_Reserved_20 : 60|4@1+ (1,0) [0|15] ""  PC

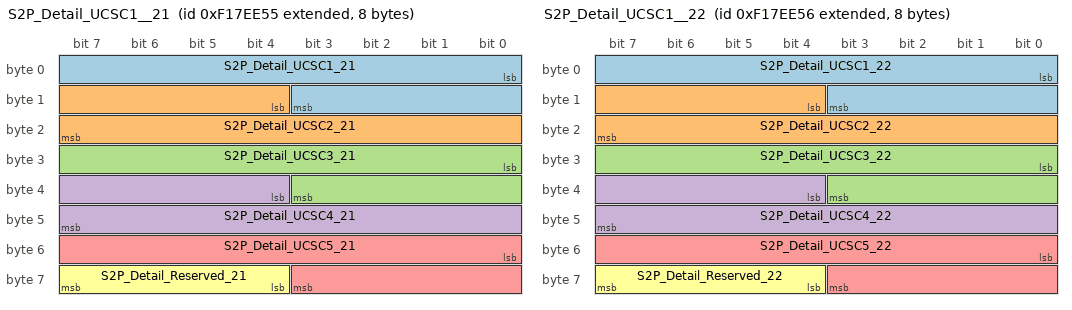
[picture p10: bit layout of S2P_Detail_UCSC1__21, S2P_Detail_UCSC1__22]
BO_ 2400710229 S2P_Detail_UCSC1__21: 8 SBMU
 SG_ S2P_Detail_UCSC1_21 : 0|12@1+ (0.1,0) [0|409.5] "V"  PC
 SG_ S2P_Detail_UCSC2_21 : 12|12@1+ (0.1,0) [0|409.5] "V"  PC
 SG_ S2P_Detail_UCSC3_21 : 24|12@1+ (0.1,0) [0|409.5] "V"  PC
 SG_ S2P_Detail_UCSC4_21 : 36|12@1+ (0.1,0) [0|409.5] "V"  PC
 SG_ S2P_Detail_UCSC5_21 : 48|12@1+ (0.1,0) [0|409.5] "V"  PC
 SG_ S2P_Detail_Reserved_21 : 60|4@1+ (1,0) [0|15] ""  PC

BO_ 2400710230 S2P_Detail_UCSC1__22: 8 SBMU
 SG_ S2P_Detail_UCSC1_22 : 0|12@1+ (0.1,0) [0|409.5] "V"  PC
 SG_ S2P_Detail_UCSC2_22 : 12|12@1+ (0.1,0) [0|409.5] "V"  PC
 SG_ S2P_Detail_UCSC3_22 : 24|12@1+ (0.1,0) [0|409.5] "V"  PC
 SG_ S2P_Detail_UCSC4_22 : 36|12@1+ (0.1,0) [0|409.5] "V"  PC
 SG_ S2P_Detail_UCSC5_22 : 48|12@1+ (0.1,0) [0|409.5] "V"  PC
 SG_ S2P_Detail_Reserved_22 : 60|4@1+ (1,0) [0|15] ""  PC

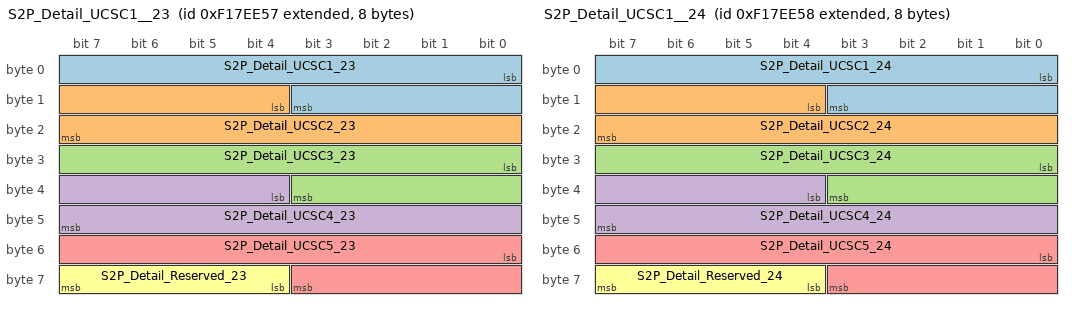
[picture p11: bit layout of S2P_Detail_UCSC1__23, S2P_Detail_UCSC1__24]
BO_ 2400710231 S2P_Detail_UCSC1__23: 8 SBMU
 SG_ S2P_Detail_UCSC1_23 : 0|12@1+ (0.1,0) [0|409.5] "V"  PC
 SG_ S2P_Detail_UCSC2_23 : 12|12@1+ (0.1,0) [0|409.5] "V"  PC
 SG_ S2P_Detail_UCSC3_23 : 24|12@1+ (0.1,0) [0|409.5] "V"  PC
 SG_ S2P_Detail_UCSC4_23 : 36|12@1+ (0.1,0) [0|409.5] "V"  PC
 SG_ S2P_Detail_UCSC5_23 : 48|12@1+ (0.1,0) [0|409.5] "V"  PC
 SG_ S2P_Detail_Reserved_23 : 60|4@1+ (1,0) [0|15] ""  PC

BO_ 2400710232 S2P_Detail_UCSC1__24: 8 SBMU
 SG_ S2P_Detail_UCSC1_24 : 0|12@1+ (0.1,0) [0|409.5] "V"  PC
 SG_ S2P_Detail_UCSC2_24 : 12|12@1+ (0.1,0) [0|409.5] "V"  PC
 SG_ S2P_Detail_UCSC3_24 : 24|12@1+ (0.1,0) [0|409.5] "V"  PC
 SG_ S2P_Detail_UCSC4_24 : 36|12@1+ (0.1,0) [0|409.5] "V"  PC
 SG_ S2P_Detail_UCSC5_24 : 48|12@1+ (0.1,0) [0|409.5] "V"  PC
 SG_ S2P_Detail_Reserved_24 : 60|4@1+ (1,0) [0|15] ""  PC

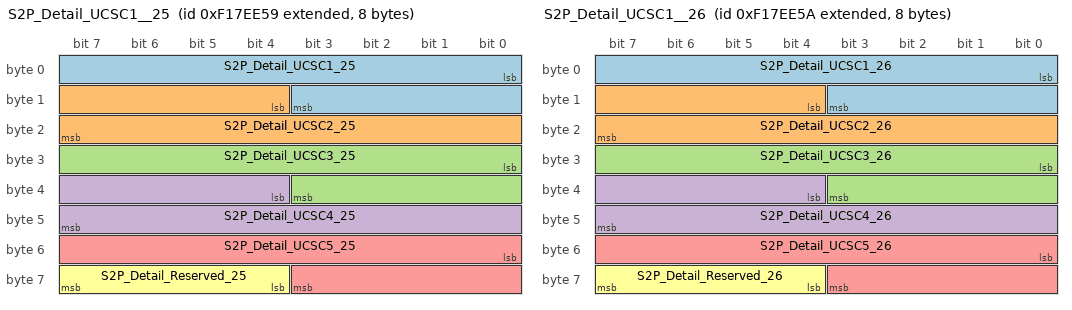
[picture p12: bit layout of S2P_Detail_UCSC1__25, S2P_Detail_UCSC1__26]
BO_ 2400710233 S2P_Detail_UCSC1__25: 8 SBMU
 SG_ S2P_Detail_UCSC1_25 : 0|12@1+ (0.1,0) [0|409.5] "V"  PC
 SG_ S2P_Detail_UCSC2_25 : 12|12@1+ (0.1,0) [0|409.5] "V"  PC
 SG_ S2P_Detail_UCSC3_25 : 24|12@1+ (0.1,0) [0|409.5] "V"  PC
 SG_ S2P_Detail_UCSC4_25 : 36|12@1+ (0.1,0) [0|409.5] "V"  PC
 SG_ S2P_Detail_UCSC5_25 : 48|12@1+ (0.1,0) [0|409.5] "V"  PC
 SG_ S2P_Detail_Reserved_25 : 60|4@1+ (1,0) [0|15] ""  PC

BO_ 2400710234 S2P_Detail_UCSC1__26: 8 SBMU
 SG_ S2P_Detail_UCSC1_26 : 0|12@1+ (0.1,0) [0|409.5] "V"  PC
 SG_ S2P_Detail_UCSC2_26 : 12|12@1+ (0.1,0) [0|409.5] "V"  PC
 SG_ S2P_Detail_UCSC3_26 : 24|12@1+ (0.1,0) [0|409.5] "V"  PC
 SG_ S2P_Detail_UCSC4_26 : 36|12@1+ (0.1,0) [0|409.5] "V"  PC
 SG_ S2P_Detail_UCSC5_26 : 48|12@1+ (0.1,0) [0|409.5] "V"  PC
 SG_ S2P_Detail_Reserved_26 : 60|4@1+ (1,0) [0|15] ""  PC

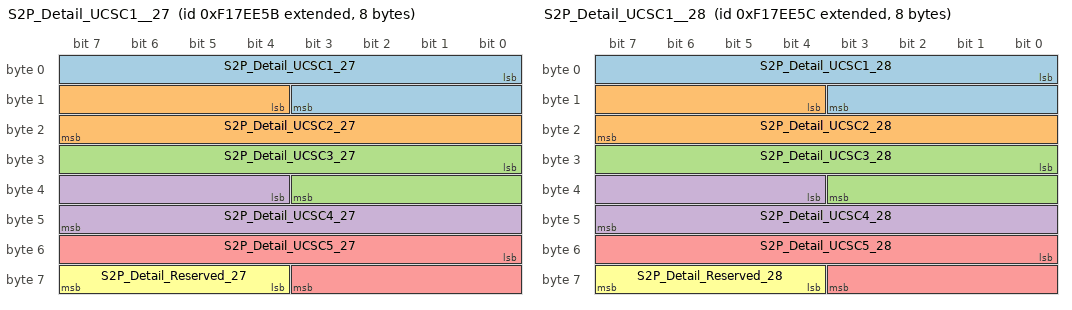
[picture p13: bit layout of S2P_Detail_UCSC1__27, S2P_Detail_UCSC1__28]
BO_ 2400710235 S2P_Detail_UCSC1__27: 8 SBMU
 SG_ S2P_Detail_UCSC1_27 : 0|12@1+ (0.1,0) [0|409.5] "V"  PC
 SG_ S2P_Detail_UCSC2_27 : 12|12@1+ (0.1,0) [0|409.5] "V"  PC
 SG_ S2P_Detail_UCSC3_27 : 24|12@1+ (0.1,0) [0|409.5] "V"  PC
 SG_ S2P_Detail_UCSC4_27 : 36|12@1+ (0.1,0) [0|409.5] "V"  PC
 SG_ S2P_Detail_UCSC5_27 : 48|12@1+ (0.1,0) [0|409.5] "V"  PC
 SG_ S2P_Detail_Reserved_27 : 60|4@1+ (1,0) [0|15] ""  PC

BO_ 2400710236 S2P_Detail_UCSC1__28: 8 SBMU
 SG_ S2P_Detail_UCSC1_28 : 0|12@1+ (0.1,0) [0|409.5] "V"  PC
 SG_ S2P_Detail_UCSC2_28 : 12|12@1+ (0.1,0) [0|409.5] "V"  PC
 SG_ S2P_Detail_UCSC3_28 : 24|12@1+ (0.1,0) [0|409.5] "V"  PC
 SG_ S2P_Detail_UCSC4_28 : 36|12@1+ (0.1,0) [0|409.5] "V"  PC
 SG_ S2P_Detail_UCSC5_28 : 48|12@1+ (0.1,0) [0|409.5] "V"  PC
 SG_ S2P_Detail_Reserved_28 : 60|4@1+ (1,0) [0|15] ""  PC

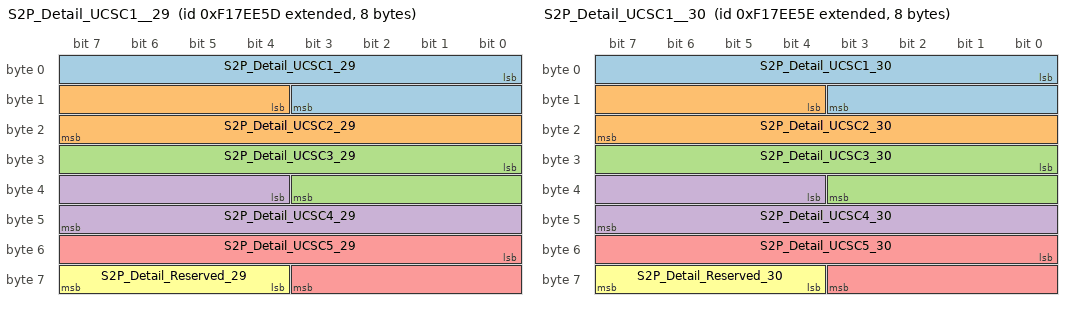
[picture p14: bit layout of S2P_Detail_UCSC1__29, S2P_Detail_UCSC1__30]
BO_ 2400710237 S2P_Detail_UCSC1__29: 8 SBMU
 SG_ S2P_Detail_UCSC1_29 : 0|12@1+ (0.1,0) [0|409.5] "V"  PC
 SG_ S2P_Detail_UCSC2_29 : 12|12@1+ (0.1,0) [0|409.5] "V"  PC
 SG_ S2P_Detail_UCSC3_29 : 24|12@1+ (0.1,0) [0|409.5] "V"  PC
 SG_ S2P_Detail_UCSC4_29 : 36|12@1+ (0.1,0) [0|409.5] "V"  PC
 SG_ S2P_Detail_UCSC5_29 : 48|12@1+ (0.1,0) [0|409.5] "V"  PC
 SG_ S2P_Detail_Reserved_29 : 60|4@1+ (1,0) [0|15] ""  PC

BO_ 2400710238 S2P_Detail_UCSC1__30: 8 SBMU
 SG_ S2P_Detail_UCSC1_30 : 0|12@1+ (0.1,0) [0|409.5] "V"  PC
 SG_ S2P_Detail_UCSC2_30 : 12|12@1+ (0.1,0) [0|409.5] "V"  PC
 SG_ S2P_Detail_UCSC3_30 : 24|12@1+ (0.1,0) [0|409.5] "V"  PC
 SG_ S2P_Detail_UCSC4_30 : 36|12@1+ (0.1,0) [0|409.5] "V"  PC
 SG_ S2P_Detail_UCSC5_30 : 48|12@1+ (0.1,0) [0|409.5] "V"  PC
 SG_ S2P_Detail_Reserved_30 : 60|4@1+ (1,0) [0|15] ""  PC

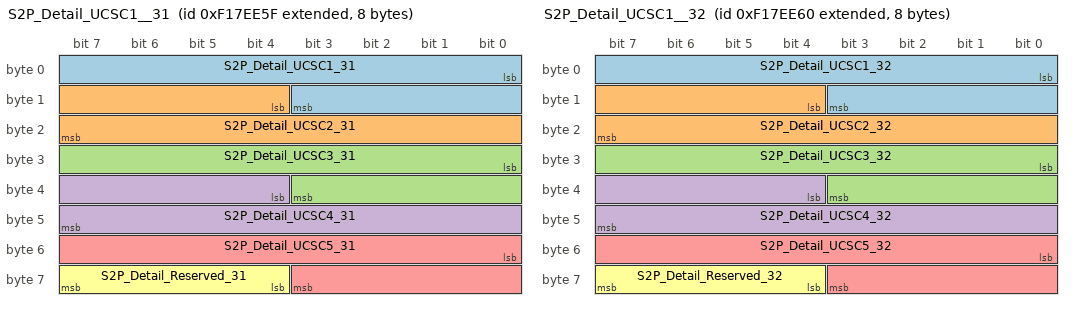
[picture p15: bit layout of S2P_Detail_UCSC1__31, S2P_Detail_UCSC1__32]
BO_ 2400710239 S2P_Detail_UCSC1__31: 8 SBMU
 SG_ S2P_Detail_UCSC1_31 : 0|12@1+ (0.1,0) [0|409.5] "V"  PC
 SG_ S2P_Detail_UCSC2_31 : 12|12@1+ (0.1,0) [0|409.5] "V"  PC
 SG_ S2P_Detail_UCSC3_31 : 24|12@1+ (0.1,0) [0|409.5] "V"  PC
 SG_ S2P_Detail_UCSC4_31 : 36|12@1+ (0.1,0) [0|409.5] "V"  PC
 SG_ S2P_Detail_UCSC5_31 : 48|12@1+ (0.1,0) [0|409.5] "V"  PC
 SG_ S2P_Detail_Reserved_31 : 60|4@1+ (1,0) [0|15] ""  PC

BO_ 2400710240 S2P_Detail_UCSC1__32: 8 SBMU
 SG_ S2P_Detail_UCSC1_32 : 0|12@1+ (0.1,0) [0|409.5] "V"  PC
 SG_ S2P_Detail_UCSC2_32 : 12|12@1+ (0.1,0) [0|409.5] "V"  PC
 SG_ S2P_Detail_UCSC3_32 : 24|12@1+ (0.1,0) [0|409.5] "V"  PC
 SG_ S2P_Detail_UCSC4_32 : 36|12@1+ (0.1,0) [0|409.5] "V"  PC
 SG_ S2P_Detail_UCSC5_32 : 48|12@1+ (0.1,0) [0|409.5] "V"  PC
 SG_ S2P_Detail_Reserved_32 : 60|4@1+ (1,0) [0|15] ""  PC

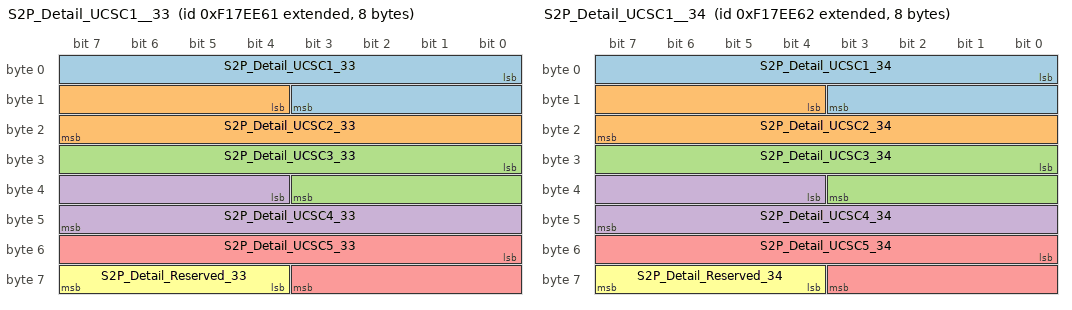
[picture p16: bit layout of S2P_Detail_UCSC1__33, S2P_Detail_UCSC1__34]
BO_ 2400710241 S2P_Detail_UCSC1__33: 8 SBMU
 SG_ S2P_Detail_UCSC1_33 : 0|12@1+ (0.1,0) [0|409.5] "V"  PC
 SG_ S2P_Detail_UCSC2_33 : 12|12@1+ (0.1,0) [0|409.5] "V"  PC
 SG_ S2P_Detail_UCSC3_33 : 24|12@1+ (0.1,0) [0|409.5] "V"  PC
 SG_ S2P_Detail_UCSC4_33 : 36|12@1+ (0.1,0) [0|409.5] "V"  PC
 SG_ S2P_Detail_UCSC5_33 : 48|12@1+ (0.1,0) [0|409.5] "V"  PC
 SG_ S2P_Detail_Reserved_33 : 60|4@1+ (1,0) [0|15] ""  PC

BO_ 2400710242 S2P_Detail_UCSC1__34: 8 SBMU
 SG_ S2P_Detail_UCSC1_34 : 0|12@1+ (0.1,0) [0|409.5] "V"  PC
 SG_ S2P_Detail_UCSC2_34 : 12|12@1+ (0.1,0) [0|409.5] "V"  PC
 SG_ S2P_Detail_UCSC3_34 : 24|12@1+ (0.1,0) [0|409.5] "V"  PC
 SG_ S2P_Detail_UCSC4_34 : 36|12@1+ (0.1,0) [0|409.5] "V"  PC
 SG_ S2P_Detail_UCSC5_34 : 48|12@1+ (0.1,0) [0|409.5] "V"  PC
 SG_ S2P_Detail_Reserved_34 : 60|4@1+ (1,0) [0|15] ""  PC

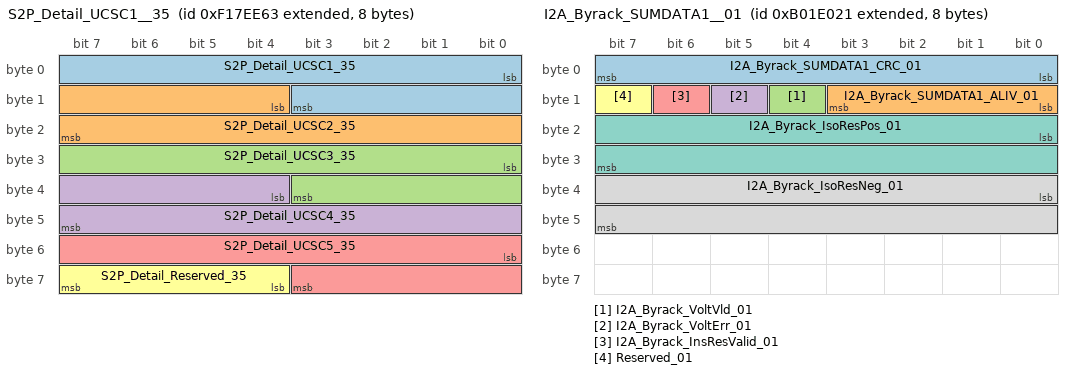
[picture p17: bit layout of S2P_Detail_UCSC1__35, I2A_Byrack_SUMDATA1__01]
BO_ 2400710243 S2P_Detail_UCSC1__35: 8 SBMU
 SG_ S2P_Detail_UCSC1_35 : 0|12@1+ (0.1,0) [0|409.5] "V"  PC
 SG_ S2P_Detail_UCSC2_35 : 12|12@1+ (0.1,0) [0|409.5] "V"  PC
 SG_ S2P_Detail_UCSC3_35 : 24|12@1+ (0.1,0) [0|409.5] "V"  PC
 SG_ S2P_Detail_UCSC4_35 : 36|12@1+ (0.1,0) [0|409.5] "V"  PC
 SG_ S2P_Detail_UCSC5_35 : 48|12@1+ (0.1,0) [0|409.5] "V"  PC
 SG_ S2P_Detail_Reserved_35 : 60|4@1+ (1,0) [0|15] ""  PC

BO_ 2400710244 S2P_Detail_UCSC1__36: 8 SBMU
 SG_ S2P_Detail_UCSC1_36 : 0|12@1+ (0.1,0) [0|409.5] "V"  PC
 SG_ S2P_Detail_UCSC2_36 : 12|12@1+ (0.1,0) [0|409.5] "V"  PC
 SG_ S2P_Detail_UCSC3_36 : 24|12@1+ (0.1,0) [0|409.5] "V"  PC
 SG_ S2P_Detail_UCSC4_36 : 36|12@1+ (0.1,0) [0|409.5] "V"  PC
 SG_ S2P_Detail_UCSC5_36 : 48|12@1+ (0.1,0) [0|409.5] "V"  PC
 SG_ S2P_Detail_Reserved_36 : 60|4@1+ (1,0) [0|15] ""  PC

BO_ 2400710245 S2P_Detail_UCSC1__37: 8 SBMU
 SG_ S2P_Detail_UCSC1_37 : 0|12@1+ (0.1,0) [0|409.5] "V"  PC
 SG_ S2P_Detail_UCSC2_37 : 12|12@1+ (0.1,0) [0|409.5] "V"  PC
 SG_ S2P_Detail_UCSC3_37 : 24|12@1+ (0.1,0) [0|409.5] "V"  PC
 SG_ S2P_Detail_UCSC4_37 : 36|12@1+ (0.1,0) [0|409.5] "V"  PC
 SG_ S2P_Detail_UCSC5_37 : 48|12@1+ (0.1,0) [0|409.5] "V"  PC
 SG_ S2P_Detail_Reserved_37 : 60|4@1+ (1,0) [0|15] ""  PC

BO_ 2400710246 S2P_Detail_UCSC1__38: 8 SBMU
 SG_ S2P_Detail_UCSC1_38 : 0|12@1+ (0.1,0) [0|409.5] "V"  PC
 SG_ S2P_Detail_UCSC2_38 : 12|12@1+ (0.1,0) [0|409.5] "V"  PC
 SG_ S2P_Detail_UCSC3_38 : 24|12@1+ (0.1,0) [0|409.5] "V"  PC
 SG_ S2P_Detail_UCSC4_38 : 36|12@1+ (0.1,0) [0|409.5] "V"  PC
 SG_ S2P_Detail_UCSC5_38 : 48|12@1+ (0.1,0) [0|409.5] "V"  PC
 SG_ S2P_Detail_Reserved_38 : 60|4@1+ (1,0) [0|15] ""  PC

BO_ 2400710247 S2P_Detail_UCSC1__39: 8 SBMU
 SG_ S2P_Detail_UCSC1_39 : 0|12@1+ (0.1,0) [0|409.5] "V"  PC
 SG_ S2P_Detail_UCSC2_39 : 12|12@1+ (0.1,0) [0|409.5] "V"  PC
 SG_ S2P_Detail_UCSC3_39 : 24|12@1+ (0.1,0) [0|409.5] "V"  PC
 SG_ S2P_Detail_UCSC4_39 : 36|12@1+ (0.1,0) [0|409.5] "V"  PC
 SG_ S2P_Detail_UCSC5_39 : 48|12@1+ (0.1,0) [0|409.5] "V"  PC
 SG_ S2P_Detail_Reserved_39 : 60|4@1+ (1,0) [0|15] ""  PC

BO_ 2400710248 S2P_Detail_UCSC1__40: 8 SBMU
 SG_ S2P_Detail_UCSC1_40 : 0|12@1+ (0.1,0) [0|409.5] "V"  PC
 SG_ S2P_Detail_UCSC2_40 : 12|12@1+ (0.1,0) [0|409.5] "V"  PC
 SG_ S2P_Detail_UCSC3_40 : 24|12@1+ (0.1,0) [0|409.5] "V"  PC
 SG_ S2P_Detail_UCSC4_40 : 36|12@1+ (0.1,0) [0|409.5] "V"  PC
 SG_ S2P_Detail_UCSC5_40 : 48|12@1+ (0.1,0) [0|409.5] "V"  PC
 SG_ S2P_Detail_Reserved_40 : 60|4@1+ (1,0) [0|15] ""  PC

BO_ 2400710249 S2P_Detail_UCSC1__41: 8 SBMU
 SG_ S2P_Detail_UCSC1_41 : 0|12@1+ (0.1,0) [0|409.5] "V"  PC
 SG_ S2P_Detail_UCSC2_41 : 12|12@1+ (0.1,0) [0|409.5] "V"  PC
 SG_ S2P_Detail_UCSC3_41 : 24|12@1+ (0.1,0) [0|409.5] "V"  PC
 SG_ S2P_Detail_UCSC4_41 : 36|12@1+ (0.1,0) [0|409.5] "V"  PC
 SG_ S2P_Detail_UCSC5_41 : 48|12@1+ (0.1,0) [0|409.5] "V"  PC
 SG_ S2P_Detail_Reserved_41 : 60|4@1+ (1,0) [0|15] ""  PC

BO_ 2400710250 S2P_Detail_UCSC1__42: 8 SBMU
 SG_ S2P_Detail_UCSC1_42 : 0|12@1+ (0.1,0) [0|409.5] "V"  PC
 SG_ S2P_Detail_UCSC2_42 : 12|12@1+ (0.1,0) [0|409.5] "V"  PC
 SG_ S2P_Detail_UCSC3_42 : 24|12@1+ (0.1,0) [0|409.5] "V"  PC
 SG_ S2P_Detail_UCSC4_42 : 36|12@1+ (0.1,0) [0|409.5] "V"  PC
 SG_ S2P_Detail_UCSC5_42 : 48|12@1+ (0.1,0) [0|409.5] "V"  PC
 SG_ S2P_Detail_Reserved_42 : 60|4@1+ (1,0) [0|15] ""  PC

BO_ 2400710251 S2P_Detail_UCSC1__43: 8 SBMU
 SG_ S2P_Detail_UCSC1_43 : 0|12@1+ (0.1,0) [0|409.5] "V"  PC
 SG_ S2P_Detail_UCSC2_43 : 12|12@1+ (0.1,0) [0|409.5] "V"  PC
 SG_ S2P_Detail_UCSC3_43 : 24|12@1+ (0.1,0) [0|409.5] "V"  PC
 SG_ S2P_Detail_UCSC4_43 : 36|12@1+ (0.1,0) [0|409.5] "V"  PC
 SG_ S2P_Detail_UCSC5_43 : 48|12@1+ (0.1,0) [0|409.5] "V"  PC
 SG_ S2P_Detail_Reserved_43 : 60|4@1+ (1,0) [0|15] ""  PC

BO_ 2400710252 S2P_Detail_UCSC1__44: 8 SBMU
 SG_ S2P_Detail_UCSC1_44 : 0|12@1+ (0.1,0) [0|409.5] "V"  PC
 SG_ S2P_Detail_UCSC2_44 : 12|12@1+ (0.1,0) [0|409.5] "V"  PC
 SG_ S2P_Detail_UCSC3_44 : 24|12@1+ (0.1,0) [0|409.5] "V"  PC
 SG_ S2P_Detail_UCSC4_44 : 36|12@1+ (0.1,0) [0|409.5] "V"  PC
 SG_ S2P_Detail_UCSC5_44 : 48|12@1+ (0.1,0) [0|409.5] "V"  PC
 SG_ S2P_Detail_Reserved_44 : 60|4@1+ (1,0) [0|15] ""  PC

BO_ 2400710253 S2P_Detail_UCSC1__45: 8 SBMU
 SG_ S2P_Detail_UCSC1_45 : 0|12@1+ (0.1,0) [0|409.5] "V"  PC
 SG_ S2P_Detail_UCSC2_45 : 12|12@1+ (0.1,0) [0|409.5] "V"  PC
 SG_ S2P_Detail_UCSC3_45 : 24|12@1+ (0.1,0) [0|409.5] "V"  PC
 SG_ S2P_Detail_UCSC4_45 : 36|12@1+ (0.1,0) [0|409.5] "V"  PC
 SG_ S2P_Detail_UCSC5_45 : 48|12@1+ (0.1,0) [0|409.5] "V"  PC
 SG_ S2P_Detail_Reserved_45 : 60|4@1+ (1,0) [0|15] ""  PC

BO_ 2400710254 S2P_Detail_UCSC1__46: 8 SBMU
 SG_ S2P_Detail_UCSC1_46 : 0|12@1+ (0.1,0) [0|409.5] "V"  PC
 SG_ S2P_Detail_UCSC2_46 : 12|12@1+ (0.1,0) [0|409.5] "V"  PC
 SG_ S2P_Detail_UCSC3_46 : 24|12@1+ (0.1,0) [0|409.5] "V"  PC
 SG_ S2P_Detail_UCSC4_46 : 36|12@1+ (0.1,0) [0|409.5] "V"  PC
 SG_ S2P_Detail_UCSC5_46 : 48|12@1+ (0.1,0) [0|409.5] "V"  PC
 SG_ S2P_Detail_Reserved_46 : 60|4@1+ (1,0) [0|15] ""  PC

BO_ 2400710255 S2P_Detail_UCSC1__47: 8 SBMU
 SG_ S2P_Detail_UCSC1_47 : 0|12@1+ (0.1,0) [0|409.5] "V"  PC
 SG_ S2P_Detail_UCSC2_47 : 12|12@1+ (0.1,0) [0|409.5] "V"  PC
 SG_ S2P_Detail_UCSC3_47 : 24|12@1+ (0.1,0) [0|409.5] "V"  PC
 SG_ S2P_Detail_UCSC4_47 : 36|12@1+ (0.1,0) [0|409.5] "V"  PC
 SG_ S2P_Detail_UCSC5_47 : 48|12@1+ (0.1,0) [0|409.5] "V"  PC
 SG_ S2P_Detail_Reserved_47 : 60|4@1+ (1,0) [0|15] ""  PC

BO_ 2400710256 S2P_Detail_UCSC1__48: 8 SBMU
 SG_ S2P_Detail_UCSC1_48 : 0|12@1+ (0.1,0) [0|409.5] "V"  PC
 SG_ S2P_Detail_UCSC2_48 : 12|12@1+ (0.1,0) [0|409.5] "V"  PC
 SG_ S2P_Detail_UCSC3_48 : 24|12@1+ (0.1,0) [0|409.5] "V"  PC
 SG_ S2P_Detail_UCSC4_48 : 36|12@1+ (0.1,0) [0|409.5] "V"  PC
 SG_ S2P_Detail_UCSC5_48 : 48|12@1+ (0.1,0) [0|409.5] "V"  PC
 SG_ S2P_Detail_Reserved_48 : 60|4@1+ (1,0) [0|15] ""  PC

BO_ 2400710257 S2P_Detail_UCSC1__49: 8 SBMU
 SG_ S2P_Detail_UCSC1_49 : 0|12@1+ (0.1,0) [0|409.5] "V"  PC
 SG_ S2P_Detail_UCSC2_49 : 12|12@1+ (0.1,0) [0|409.5] "V"  PC
 SG_ S2P_Detail_UCSC3_49 : 24|12@1+ (0.1,0) [0|409.5] "V"  PC
 SG_ S2P_Detail_UCSC4_49 : 36|12@1+ (0.1,0) [0|409.5] "V"  PC
 SG_ S2P_Detail_UCSC5_49 : 48|12@1+ (0.1,0) [0|409.5] "V"  PC
 SG_ S2P_Detail_Reserved_49 : 60|4@1+ (1,0) [0|15] ""  PC

BO_ 2400710258 S2P_Detail_UCSC1__50: 8 SBMU
 SG_ S2P_Detail_UCSC1_50 : 0|12@1+ (0.1,0) [0|409.5] "V"  PC
 SG_ S2P_Detail_UCSC2_50 : 12|12@1+ (0.1,0) [0|409.5] "V"  PC
 SG_ S2P_Detail_UCSC3_50 : 24|12@1+ (0.1,0) [0|409.5] "V"  PC
 SG_ S2P_Detail_UCSC4_50 : 36|12@1+ (0.1,0) [0|409.5] "V"  PC
 SG_ S2P_Detail_UCSC5_50 : 48|12@1+ (0.1,0) [0|409.5] "V"  PC
 SG_ S2P_Detail_Reserved_50 : 60|4@1+ (1,0) [0|15] ""  PC

BO_ 2400710259 S2P_Detail_UCSC1__51: 8 SBMU
 SG_ S2P_Detail_UCSC1_51 : 0|12@1+ (0.1,0) [0|409.5] "V"  PC
 SG_ S2P_Detail_UCSC2_51 : 12|12@1+ (0.1,0) [0|409.5] "V"  PC
 SG_ S2P_Detail_UCSC3_51 : 24|12@1+ (0.1,0) [0|409.5] "V"  PC
 SG_ S2P_Detail_UCSC4_51 : 36|12@1+ (0.1,0) [0|409.5] "V"  PC
 SG_ S2P_Detail_UCSC5_51 : 48|12@1+ (0.1,0) [0|409.5] "V"  PC
 SG_ S2P_Detail_Reserved_51 : 60|4@1+ (1,0) [0|15] ""  PC

BO_ 2400710260 S2P_Detail_UCSC1__52: 8 SBMU
 SG_ S2P_Detail_UCSC1_52 : 0|12@1+ (0.1,0) [0|409.5] "V"  PC
 SG_ S2P_Detail_UCSC2_52 : 12|12@1+ (0.1,0) [0|409.5] "V"  PC
 SG_ S2P_Detail_UCSC3_52 : 24|12@1+ (0.1,0) [0|409.5] "V"  PC
 SG_ S2P_Detail_UCSC4_52 : 36|12@1+ (0.1,0) [0|409.5] "V"  PC
 SG_ S2P_Detail_UCSC5_52 : 48|12@1+ (0.1,0) [0|409.5] "V"  PC
 SG_ S2P_Detail_Reserved_52 : 60|4@1+ (1,0) [0|15] ""  PC

BO_ 2400710261 S2P_Detail_UCSC1__53: 8 SBMU
 SG_ S2P_Detail_UCSC1_53 : 0|12@1+ (0.1,0) [0|409.5] "V"  PC
 SG_ S2P_Detail_UCSC2_53 : 12|12@1+ (0.1,0) [0|409.5] "V"  PC
 SG_ S2P_Detail_UCSC3_53 : 24|12@1+ (0.1,0) [0|409.5] "V"  PC
 SG_ S2P_Detail_UCSC4_53 : 36|12@1+ (0.1,0) [0|409.5] "V"  PC
 SG_ S2P_Detail_UCSC5_53 : 48|12@1+ (0.1,0) [0|409.5] "V"  PC
 SG_ S2P_Detail_Reserved_53 : 60|4@1+ (1,0) [0|15] ""  PC

BO_ 2400710262 S2P_Detail_UCSC1__54: 8 SBMU
 SG_ S2P_Detail_UCSC1_54 : 0|12@1+ (0.1,0) [0|409.5] "V"  PC
 SG_ S2P_Detail_UCSC2_54 : 12|12@1+ (0.1,0) [0|409.5] "V"  PC
 SG_ S2P_Detail_UCSC3_54 : 24|12@1+ (0.1,0) [0|409.5] "V"  PC
 SG_ S2P_Detail_UCSC4_54 : 36|12@1+ (0.1,0) [0|409.5] "V"  PC
 SG_ S2P_Detail_UCSC5_54 : 48|12@1+ (0.1,0) [0|409.5] "V"  PC
 SG_ S2P_Detail_Reserved_54 : 60|4@1+ (1,0) [0|15] ""  PC

BO_ 2400710263 S2P_Detail_UCSC1__55: 8 SBMU
 SG_ S2P_Detail_UCSC1_55 : 0|12@1+ (0.1,0) [0|409.5] "V"  PC
 SG_ S2P_Detail_UCSC2_55 : 12|12@1+ (0.1,0) [0|409.5] "V"  PC
 SG_ S2P_Detail_UCSC3_55 : 24|12@1+ (0.1,0) [0|409.5] "V"  PC
 SG_ S2P_Detail_UCSC4_55 : 36|12@1+ (0.1,0) [0|409.5] "V"  PC
 SG_ S2P_Detail_UCSC5_55 : 48|12@1+ (0.1,0) [0|409.5] "V"  PC
 SG_ S2P_Detail_Reserved_55 : 60|4@1+ (1,0) [0|15] ""  PC

BO_ 2400710264 S2P_Detail_UCSC1__56: 8 SBMU
 SG_ S2P_Detail_UCSC1_56 : 0|12@1+ (0.1,0) [0|409.5] "V"  PC
 SG_ S2P_Detail_UCSC2_56 : 12|12@1+ (0.1,0) [0|409.5] "V"  PC
 SG_ S2P_Detail_UCSC3_56 : 24|12@1+ (0.1,0) [0|409.5] "V"  PC
 SG_ S2P_Detail_UCSC4_56 : 36|12@1+ (0.1,0) [0|409.5] "V"  PC
 SG_ S2P_Detail_UCSC5_56 : 48|12@1+ (0.1,0) [0|409.5] "V"  PC
 SG_ S2P_Detail_Reserved_56 : 60|4@1+ (1,0) [0|15] ""  PC

BO_ 2400710265 S2P_Detail_UCSC1__57: 8 SBMU
 SG_ S2P_Detail_UCSC1_57 : 0|12@1+ (0.1,0) [0|409.5] "V"  PC
 SG_ S2P_Detail_UCSC2_57 : 12|12@1+ (0.1,0) [0|409.5] "V"  PC
 SG_ S2P_Detail_UCSC3_57 : 24|12@1+ (0.1,0) [0|409.5] "V"  PC
 SG_ S2P_Detail_UCSC4_57 : 36|12@1+ (0.1,0) [0|409.5] "V"  PC
 SG_ S2P_Detail_UCSC5_57 : 48|12@1+ (0.1,0) [0|409.5] "V"  PC
 SG_ S2P_Detail_Reserved_57 : 60|4@1+ (1,0) [0|15] ""  PC

BO_ 2400710266 S2P_Detail_UCSC1__58: 8 SBMU
 SG_ S2P_Detail_UCSC1_58 : 0|12@1+ (0.1,0) [0|409.5] "V"  PC
 SG_ S2P_Detail_UCSC2_58 : 12|12@1+ (0.1,0) [0|409.5] "V"  PC
 SG_ S2P_Detail_UCSC3_58 : 24|12@1+ (0.1,0) [0|409.5] "V"  PC
 SG_ S2P_Detail_UCSC4_58 : 36|12@1+ (0.1,0) [0|409.5] "V"  PC
 SG_ S2P_Detail_UCSC5_58 : 48|12@1+ (0.1,0) [0|409.5] "V"  PC
 SG_ S2P_Detail_Reserved_58 : 60|4@1+ (1,0) [0|15] ""  PC

BO_ 2400710267 S2P_Detail_UCSC1__59: 8 SBMU
 SG_ S2P_Detail_UCSC1_59 : 0|12@1+ (0.1,0) [0|409.5] "V"  PC
 SG_ S2P_Detail_UCSC2_59 : 12|12@1+ (0.1,0) [0|409.5] "V"  PC
 SG_ S2P_Detail_UCSC3_59 : 24|12@1+ (0.1,0) [0|409.5] "V"  PC
 SG_ S2P_Detail_UCSC4_59 : 36|12@1+ (0.1,0) [0|409.5] "V"  PC
 SG_ S2P_Detail_UCSC5_59 : 48|12@1+ (0.1,0) [0|409.5] "V"  PC
 SG_ S2P_Detail_Reserved_59 : 60|4@1+ (1,0) [0|15] ""  PC

BO_ 2400710268 S2P_Detail_UCSC1__60: 8 SBMU
 SG_ S2P_Detail_UCSC1_60 : 0|12@1+ (0.1,0) [0|409.5] "V"  PC
 SG_ S2P_Detail_UCSC2_60 : 12|12@1+ (0.1,0) [0|409.5] "V"  PC
 SG_ S2P_Detail_UCSC3_60 : 24|12@1+ (0.1,0) [0|409.5] "V"  PC
 SG_ S2P_Detail_UCSC4_60 : 36|12@1+ (0.1,0) [0|409.5] "V"  PC
 SG_ S2P_Detail_UCSC5_60 : 48|12@1+ (0.1,0) [0|409.5] "V"  PC
 SG_ S2P_Detail_Reserved_60 : 60|4@1+ (1,0) [0|15] ""  PC

BO_ 2400710269 S2P_Detail_UCSC1__61: 8 SBMU
 SG_ S2P_Detail_UCSC1_61 : 0|12@1+ (0.1,0) [0|409.5] "V"  PC
 SG_ S2P_Detail_UCSC2_61 : 12|12@1+ (0.1,0) [0|409.5] "V"  PC
 SG_ S2P_Detail_UCSC3_61 : 24|12@1+ (0.1,0) [0|409.5] "V"  PC
 SG_ S2P_Detail_UCSC4_61 : 36|12@1+ (0.1,0) [0|409.5] "V"  PC
 SG_ S2P_Detail_UCSC5_61 : 48|12@1+ (0.1,0) [0|409.5] "V"  PC
 SG_ S2P_Detail_Reserved_61 : 60|4@1+ (1,0) [0|15] ""  PC

BO_ 2400710270 S2P_Detail_UCSC1__62: 8 SBMU
 SG_ S2P_Detail_UCSC1_62 : 0|12@1+ (0.1,0) [0|409.5] "V"  PC
 SG_ S2P_Detail_UCSC2_62 : 12|12@1+ (0.1,0) [0|409.5] "V"  PC
 SG_ S2P_Detail_UCSC3_62 : 24|12@1+ (0.1,0) [0|409.5] "V"  PC
 SG_ S2P_Detail_UCSC4_62 : 36|12@1+ (0.1,0) [0|409.5] "V"  PC
 SG_ S2P_Detail_UCSC5_62 : 48|12@1+ (0.1,0) [0|409.5] "V"  PC
 SG_ S2P_Detail_Reserved_62 : 60|4@1+ (1,0) [0|15] ""  PC

BO_ 2400710271 S2P_Detail_UCSC1__63: 8 SBMU
 SG_ S2P_Detail_UCSC1_63 : 0|12@1+ (0.1,0) [0|409.5] "V"  PC
 SG_ S2P_Detail_UCSC2_63 : 12|12@1+ (0.1,0) [0|409.5] "V"  PC
 SG_ S2P_Detail_UCSC3_63 : 24|12@1+ (0.1,0) [0|409.5] "V"  PC
 SG_ S2P_Detail_UCSC4_63 : 36|12@1+ (0.1,0) [0|409.5] "V"  PC
 SG_ S2P_Detail_UCSC5_63 : 48|12@1+ (0.1,0) [0|409.5] "V"  PC
 SG_ S2P_Detail_Reserved_63 : 60|4@1+ (1,0) [0|15] ""  PC

BO_ 2400775745 S2P_Detail_UCSC2__01: 8 SBMU
 SG_ S2P_Detail_UCSC6_01 : 0|12@1+ (0.1,0) [0|409.5] "V"  PC
 SG_ S2P_Detail_UCSC7_01 : 12|12@1+ (0.1,0) [0|409.5] "V"  PC
 SG_ S2P_Detail_UCSC8_01 : 24|12@1+ (0.1,0) [0|409.5] "V"  PC
 SG_ S2P_Detail_Reserved_01 : 36|28@1+ (1,0) [0|268435455] ""  PC

BO_ 2400775746 S2P_Detail_UCSC2__02: 8 SBMU
 SG_ S2P_Detail_UCSC6_02 : 0|12@1+ (0.1,0) [0|409.5] "V"  PC
 SG_ S2P_Detail_UCSC7_02 : 12|12@1+ (0.1,0) [0|409.5] "V"  PC
 SG_ S2P_Detail_UCSC8_02 : 24|12@1+ (0.1,0) [0|409.5] "V"  PC
 SG_ S2P_Detail_Reserved_02 : 36|28@1+ (1,0) [0|268435455] ""  PC

BO_ 2400775747 S2P_Detail_UCSC2__03: 8 SBMU
 SG_ S2P_Detail_UCSC6_03 : 0|12@1+ (0.1,0) [0|409.5] "V"  PC
 SG_ S2P_Detail_UCSC7_03 : 12|12@1+ (0.1,0) [0|409.5] "V"  PC
 SG_ S2P_Detail_UCSC8_03 : 24|12@1+ (0.1,0) [0|409.5] "V"  PC
 SG_ S2P_Detail_Reserved_03 : 36|28@1+ (1,0) [0|268435455] ""  PC

BO_ 2400775748 S2P_Detail_UCSC2__04: 8 SBMU
 SG_ S2P_Detail_UCSC6_04 : 0|12@1+ (0.1,0) [0|409.5] "V"  PC
 SG_ S2P_Detail_UCSC7_04 : 12|12@1+ (0.1,0) [0|409.5] "V"  PC
 SG_ S2P_Detail_UCSC8_04 : 24|12@1+ (0.1,0) [0|409.5] "V"  PC
 SG_ S2P_Detail_Reserved_04 : 36|28@1+ (1,0) [0|268435455] ""  PC

BO_ 2400775749 S2P_Detail_UCSC2__05: 8 SBMU
 SG_ S2P_Detail_UCSC6_05 : 0|12@1+ (0.1,0) [0|409.5] "V"  PC
 SG_ S2P_Detail_UCSC7_05 : 12|12@1+ (0.1,0) [0|409.5] "V"  PC
 SG_ S2P_Detail_UCSC8_05 : 24|12@1+ (0.1,0) [0|409.5] "V"  PC
 SG_ S2P_Detail_Reserved_05 : 36|28@1+ (1,0) [0|268435455] ""  PC

BO_ 2400775750 S2P_Detail_UCSC2__06: 8 SBMU
 SG_ S2P_Detail_UCSC6_06 : 0|12@1+ (0.1,0) [0|409.5] "V"  PC
 SG_ S2P_Detail_UCSC7_06 : 12|12@1+ (0.1,0) [0|409.5] "V"  PC
 SG_ S2P_Detail_UCSC8_06 : 24|12@1+ (0.1,0) [0|409.5] "V"  PC
 SG_ S2P_Detail_Reserved_06 : 36|28@1+ (1,0) [0|268435455] ""  PC

BO_ 2400775751 S2P_Detail_UCSC2__07: 8 SBMU
 SG_ S2P_Detail_UCSC6_07 : 0|12@1+ (0.1,0) [0|409.5] "V"  PC
 SG_ S2P_Detail_UCSC7_07 : 12|12@1+ (0.1,0) [0|409.5] "V"  PC
 SG_ S2P_Detail_UCSC8_07 : 24|12@1+ (0.1,0) [0|409.5] "V"  PC
 SG_ S2P_Detail_Reserved_07 : 36|28@1+ (1,0) [0|268435455] ""  PC

BO_ 2400775752 S2P_Detail_UCSC2__08: 8 SBMU
 SG_ S2P_Detail_UCSC6_08 : 0|12@1+ (0.1,0) [0|409.5] "V"  PC
 SG_ S2P_Detail_UCSC7_08 : 12|12@1+ (0.1,0) [0|409.5] "V"  PC
 SG_ S2P_Detail_UCSC8_08 : 24|12@1+ (0.1,0) [0|409.5] "V"  PC
 SG_ S2P_Detail_Reserved_08 : 36|28@1+ (1,0) [0|268435455] ""  PC

BO_ 2400775753 S2P_Detail_UCSC2__09: 8 SBMU
 SG_ S2P_Detail_UCSC6_09 : 0|12@1+ (0.1,0) [0|409.5] "V"  PC
 SG_ S2P_Detail_UCSC7_09 : 12|12@1+ (0.1,0) [0|409.5] "V"  PC
 SG_ S2P_Detail_UCSC8_09 : 24|12@1+ (0.1,0) [0|409.5] "V"  PC
 SG_ S2P_Detail_Reserved_09 : 36|28@1+ (1,0) [0|268435455] ""  PC

BO_ 2400775754 S2P_Detail_UCSC2__10: 8 SBMU
 SG_ S2P_Detail_UCSC6_10 : 0|12@1+ (0.1,0) [0|409.5] "V"  PC
 SG_ S2P_Detail_UCSC7_10 : 12|12@1+ (0.1,0) [0|409.5] "V"  PC
 SG_ S2P_Detail_UCSC8_10 : 24|12@1+ (0.1,0) [0|409.5] "V"  PC
 SG_ S2P_Detail_Reserved_10 : 36|28@1+ (1,0) [0|268435455] ""  PC

BO_ 2400775755 S2P_Detail_UCSC2__11: 8 SBMU
 SG_ S2P_Detail_UCSC6_11 : 0|12@1+ (0.1,0) [0|409.5] "V"  PC
 SG_ S2P_Detail_UCSC7_11 : 12|12@1+ (0.1,0) [0|409.5] "V"  PC
 SG_ S2P_Detail_UCSC8_11 : 24|12@1+ (0.1,0) [0|409.5] "V"  PC
 SG_ S2P_Detail_Reserved_11 : 36|28@1+ (1,0) [0|268435455] ""  PC

BO_ 2400775756 S2P_Detail_UCSC2__12: 8 SBMU
 SG_ S2P_Detail_UCSC6_12 : 0|12@1+ (0.1,0) [0|409.5] "V"  PC
 SG_ S2P_Detail_UCSC7_12 : 12|12@1+ (0.1,0) [0|409.5] "V"  PC
 SG_ S2P_Detail_UCSC8_12 : 24|12@1+ (0.1,0) [0|409.5] "V"  PC
 SG_ S2P_Detail_Reserved_12 : 36|28@1+ (1,0) [0|268435455] ""  PC

BO_ 2400775757 S2P_Detail_UCSC2__13: 8 SBMU
 SG_ S2P_Detail_UCSC6_13 : 0|12@1+ (0.1,0) [0|409.5] "V"  PC
 SG_ S2P_Detail_UCSC7_13 : 12|12@1+ (0.1,0) [0|409.5] "V"  PC
 SG_ S2P_Detail_UCSC8_13 : 24|12@1+ (0.1,0) [0|409.5] "V"  PC
 SG_ S2P_Detail_Reserved_13 : 36|28@1+ (1,0) [0|268435455] ""  PC

BO_ 2400775758 S2P_Detail_UCSC2__14: 8 SBMU
 SG_ S2P_Detail_UCSC6_14 : 0|12@1+ (0.1,0) [0|409.5] "V"  PC
 SG_ S2P_Detail_UCSC7_14 : 12|12@1+ (0.1,0) [0|409.5] "V"  PC
 SG_ S2P_Detail_UCSC8_14 : 24|12@1+ (0.1,0) [0|409.5] "V"  PC
 SG_ S2P_Detail_Reserved_14 : 36|28@1+ (1,0) [0|268435455] ""  PC

BO_ 2400775759 S2P_Detail_UCSC2__15: 8 SBMU
 SG_ S2P_Detail_UCSC6_15 : 0|12@1+ (0.1,0) [0|409.5] "V"  PC
 SG_ S2P_Detail_UCSC7_15 : 12|12@1+ (0.1,0) [0|409.5] "V"  PC
 SG_ S2P_Detail_UCSC8_15 : 24|12@1+ (0.1,0) [0|409.5] "V"  PC
 SG_ S2P_Detail_Reserved_15 : 36|28@1+ (1,0) [0|268435455] ""  PC

BO_ 2400775760 S2P_Detail_UCSC2__16: 8 SBMU
 SG_ S2P_Detail_UCSC6_16 : 0|12@1+ (0.1,0) [0|409.5] "V"  PC
 SG_ S2P_Detail_UCSC7_16 : 12|12@1+ (0.1,0) [0|409.5] "V"  PC
 SG_ S2P_Detail_UCSC8_16 : 24|12@1+ (0.1,0) [0|409.5] "V"  PC
 SG_ S2P_Detail_Reserved_16 : 36|28@1+ (1,0) [0|268435455] ""  PC

BO_ 2400775761 S2P_Detail_UCSC2__17: 8 SBMU
 SG_ S2P_Detail_UCSC6_17 : 0|12@1+ (0.1,0) [0|409.5] "V"  PC
 SG_ S2P_Detail_UCSC7_17 : 12|12@1+ (0.1,0) [0|409.5] "V"  PC
 SG_ S2P_Detail_UCSC8_17 : 24|12@1+ (0.1,0) [0|409.5] "V"  PC
 SG_ S2P_Detail_Reserved_17 : 36|28@1+ (1,0) [0|268435455] ""  PC

BO_ 2400775762 S2P_Detail_UCSC2__18: 8 SBMU
 SG_ S2P_Detail_UCSC6_18 : 0|12@1+ (0.1,0) [0|409.5] "V"  PC
 SG_ S2P_Detail_UCSC7_18 : 12|12@1+ (0.1,0) [0|409.5] "V"  PC
 SG_ S2P_Detail_UCSC8_18 : 24|12@1+ (0.1,0) [0|409.5] "V"  PC
 SG_ S2P_Detail_Reserved_18 : 36|28@1+ (1,0) [0|268435455] ""  PC

BO_ 2400775763 S2P_Detail_UCSC2__19: 8 SBMU
 SG_ S2P_Detail_UCSC6_19 : 0|12@1+ (0.1,0) [0|409.5] "V"  PC
 SG_ S2P_Detail_UCSC7_19 : 12|12@1+ (0.1,0) [0|409.5] "V"  PC
 SG_ S2P_Detail_UCSC8_19 : 24|12@1+ (0.1,0) [0|409.5] "V"  PC
 SG_ S2P_Detail_Reserved_19 : 36|28@1+ (1,0) [0|268435455] ""  PC

BO_ 2400775764 S2P_Detail_UCSC2__20: 8 SBMU
 SG_ S2P_Detail_UCSC6_20 : 0|12@1+ (0.1,0) [0|409.5] "V"  PC
 SG_ S2P_Detail_UCSC7_20 : 12|12@1+ (0.1,0) [0|409.5] "V"  PC
 SG_ S2P_Detail_UCSC8_20 : 24|12@1+ (0.1,0) [0|409.5] "V"  PC
 SG_ S2P_Detail_Reserved_20 : 36|28@1+ (1,0) [0|268435455] ""  PC

BO_ 2400775765 S2P_Detail_UCSC2__21: 8 SBMU
 SG_ S2P_Detail_UCSC6_21 : 0|12@1+ (0.1,0) [0|409.5] "V"  PC
 SG_ S2P_Detail_UCSC7_21 : 12|12@1+ (0.1,0) [0|409.5] "V"  PC
 SG_ S2P_Detail_UCSC8_21 : 24|12@1+ (0.1,0) [0|409.5] "V"  PC
 SG_ S2P_Detail_Reserved_21 : 36|28@1+ (1,0) [0|268435455] ""  PC

BO_ 2400775766 S2P_Detail_UCSC2__22: 8 SBMU
 SG_ S2P_Detail_UCSC6_22 : 0|12@1+ (0.1,0) [0|409.5] "V"  PC
 SG_ S2P_Detail_UCSC7_22 : 12|12@1+ (0.1,0) [0|409.5] "V"  PC
 SG_ S2P_Detail_UCSC8_22 : 24|12@1+ (0.1,0) [0|409.5] "V"  PC
 SG_ S2P_Detail_Reserved_22 : 36|28@1+ (1,0) [0|268435455] ""  PC

BO_ 2400775767 S2P_Detail_UCSC2__23: 8 SBMU
 SG_ S2P_Detail_UCSC6_23 : 0|12@1+ (0.1,0) [0|409.5] "V"  PC
 SG_ S2P_Detail_UCSC7_23 : 12|12@1+ (0.1,0) [0|409.5] "V"  PC
 SG_ S2P_Detail_UCSC8_23 : 24|12@1+ (0.1,0) [0|409.5] "V"  PC
 SG_ S2P_Detail_Reserved_23 : 36|28@1+ (1,0) [0|268435455] ""  PC

BO_ 2400775768 S2P_Detail_UCSC2__24: 8 SBMU
 SG_ S2P_Detail_UCSC6_24 : 0|12@1+ (0.1,0) [0|409.5] "V"  PC
 SG_ S2P_Detail_UCSC7_24 : 12|12@1+ (0.1,0) [0|409.5] "V"  PC
 SG_ S2P_Detail_UCSC8_24 : 24|12@1+ (0.1,0) [0|409.5] "V"  PC
 SG_ S2P_Detail_Reserved_24 : 36|28@1+ (1,0) [0|268435455] ""  PC

BO_ 2400775769 S2P_Detail_UCSC2__25: 8 SBMU
 SG_ S2P_Detail_UCSC6_25 : 0|12@1+ (0.1,0) [0|409.5] "V"  PC
 SG_ S2P_Detail_UCSC7_25 : 12|12@1+ (0.1,0) [0|409.5] "V"  PC
 SG_ S2P_Detail_UCSC8_25 : 24|12@1+ (0.1,0) [0|409.5] "V"  PC
 SG_ S2P_Detail_Reserved_25 : 36|28@1+ (1,0) [0|268435455] ""  PC

BO_ 2400775770 S2P_Detail_UCSC2__26: 8 SBMU
 SG_ S2P_Detail_UCSC6_26 : 0|12@1+ (0.1,0) [0|409.5] "V"  PC
 SG_ S2P_Detail_UCSC7_26 : 12|12@1+ (0.1,0) [0|409.5] "V"  PC
 SG_ S2P_Detail_UCSC8_26 : 24|12@1+ (0.1,0) [0|409.5] "V"  PC
 SG_ S2P_Detail_Reserved_26 : 36|28@1+ (1,0) [0|268435455] ""  PC

BO_ 2400775771 S2P_Detail_UCSC2__27: 8 SBMU
 SG_ S2P_Detail_UCSC6_27 : 0|12@1+ (0.1,0) [0|409.5] "V"  PC
 SG_ S2P_Detail_UCSC7_27 : 12|12@1+ (0.1,0) [0|409.5] "V"  PC
 SG_ S2P_Detail_UCSC8_27 : 24|12@1+ (0.1,0) [0|409.5] "V"  PC
 SG_ S2P_Detail_Reserved_27 : 36|28@1+ (1,0) [0|268435455] ""  PC

BO_ 2400775772 S2P_Detail_UCSC2__28: 8 SBMU
 SG_ S2P_Detail_UCSC6_28 : 0|12@1+ (0.1,0) [0|409.5] "V"  PC
 SG_ S2P_Detail_UCSC7_28 : 12|12@1+ (0.1,0) [0|409.5] "V"  PC
 SG_ S2P_Detail_UCSC8_28 : 24|12@1+ (0.1,0) [0|409.5] "V"  PC
 SG_ S2P_Detail_Reserved_28 : 36|28@1+ (1,0) [0|268435455] ""  PC

BO_ 2400775773 S2P_Detail_UCSC2__29: 8 SBMU
 SG_ S2P_Detail_UCSC6_29 : 0|12@1+ (0.1,0) [0|409.5] "V"  PC
 SG_ S2P_Detail_UCSC7_29 : 12|12@1+ (0.1,0) [0|409.5] "V"  PC
 SG_ S2P_Detail_UCSC8_29 : 24|12@1+ (0.1,0) [0|409.5] "V"  PC
 SG_ S2P_Detail_Reserved_29 : 36|28@1+ (1,0) [0|268435455] ""  PC

BO_ 2400775774 S2P_Detail_UCSC2__30: 8 SBMU
 SG_ S2P_Detail_UCSC6_30 : 0|12@1+ (0.1,0) [0|409.5] "V"  PC
 SG_ S2P_Detail_UCSC7_30 : 12|12@1+ (0.1,0) [0|409.5] "V"  PC
 SG_ S2P_Detail_UCSC8_30 : 24|12@1+ (0.1,0) [0|409.5] "V"  PC
 SG_ S2P_Detail_Reserved_30 : 36|28@1+ (1,0) [0|268435455] ""  PC

BO_ 2400775775 S2P_Detail_UCSC2__31: 8 SBMU
 SG_ S2P_Detail_UCSC6_31 : 0|12@1+ (0.1,0) [0|409.5] "V"  PC
 SG_ S2P_Detail_UCSC7_31 : 12|12@1+ (0.1,0) [0|409.5] "V"  PC
 SG_ S2P_Detail_UCSC8_31 : 24|12@1+ (0.1,0) [0|409.5] "V"  PC
 SG_ S2P_Detail_Reserved_31 : 36|28@1+ (1,0) [0|268435455] ""  PC

BO_ 2400775776 S2P_Detail_UCSC2__32: 8 SBMU
 SG_ S2P_Detail_UCSC6_32 : 0|12@1+ (0.1,0) [0|409.5] "V"  PC
 SG_ S2P_Detail_UCSC7_32 : 12|12@1+ (0.1,0) [0|409.5] "V"  PC
 SG_ S2P_Detail_UCSC8_32 : 24|12@1+ (0.1,0) [0|409.5] "V"  PC
 SG_ S2P_Detail_Reserved_32 : 36|28@1+ (1,0) [0|268435455] ""  PC

BO_ 2400775777 S2P_Detail_UCSC2__33: 8 SBMU
 SG_ S2P_Detail_UCSC6_33 : 0|12@1+ (0.1,0) [0|409.5] "V"  PC
 SG_ S2P_Detail_UCSC7_33 : 12|12@1+ (0.1,0) [0|409.5] "V"  PC
 SG_ S2P_Detail_UCSC8_33 : 24|12@1+ (0.1,0) [0|409.5] "V"  PC
 SG_ S2P_Detail_Reserved_33 : 36|28@1+ (1,0) [0|268435455] ""  PC

BO_ 2400775778 S2P_Detail_UCSC2__34: 8 SBMU
 SG_ S2P_Detail_UCSC6_34 : 0|12@1+ (0.1,0) [0|409.5] "V"  PC
 SG_ S2P_Detail_UCSC7_34 : 12|12@1+ (0.1,0) [0|409.5] "V"  PC
 SG_ S2P_Detail_UCSC8_34 : 24|12@1+ (0.1,0) [0|409.5] "V"  PC
 SG_ S2P_Detail_Reserved_34 : 36|28@1+ (1,0) [0|268435455] ""  PC

BO_ 2400775779 S2P_Detail_UCSC2__35: 8 SBMU
 SG_ S2P_Detail_UCSC6_35 : 0|12@1+ (0.1,0) [0|409.5] "V"  PC
 SG_ S2P_Detail_UCSC7_35 : 12|12@1+ (0.1,0) [0|409.5] "V"  PC
 SG_ S2P_Detail_UCSC8_35 : 24|12@1+ (0.1,0) [0|409.5] "V"  PC
 SG_ S2P_Detail_Reserved_35 : 36|28@1+ (1,0) [0|268435455] ""  PC

BO_ 2400775780 S2P_Detail_UCSC2__36: 8 SBMU
 SG_ S2P_Detail_UCSC6_36 : 0|12@1+ (0.1,0) [0|409.5] "V"  PC
 SG_ S2P_Detail_UCSC7_36 : 12|12@1+ (0.1,0) [0|409.5] "V"  PC
 SG_ S2P_Detail_UCSC8_36 : 24|12@1+ (0.1,0) [0|409.5] "V"  PC
 SG_ S2P_Detail_Reserved_36 : 36|28@1+ (1,0) [0|268435455] ""  PC

BO_ 2400775781 S2P_Detail_UCSC2__37: 8 SBMU
 SG_ S2P_Detail_UCSC6_37 : 0|12@1+ (0.1,0) [0|409.5] "V"  PC
 SG_ S2P_Detail_UCSC7_37 : 12|12@1+ (0.1,0) [0|409.5] "V"  PC
 SG_ S2P_Detail_UCSC8_37 : 24|12@1+ (0.1,0) [0|409.5] "V"  PC
 SG_ S2P_Detail_Reserved_37 : 36|28@1+ (1,0) [0|268435455] ""  PC

BO_ 2400775782 S2P_Detail_UCSC2__38: 8 SBMU
 SG_ S2P_Detail_UCSC6_38 : 0|12@1+ (0.1,0) [0|409.5] "V"  PC
 SG_ S2P_Detail_UCSC7_38 : 12|12@1+ (0.1,0) [0|409.5] "V"  PC
 SG_ S2P_Detail_UCSC8_38 : 24|12@1+ (0.1,0) [0|409.5] "V"  PC
 SG_ S2P_Detail_Reserved_38 : 36|28@1+ (1,0) [0|268435455] ""  PC

BO_ 2400775783 S2P_Detail_UCSC2__39: 8 SBMU
 SG_ S2P_Detail_UCSC6_39 : 0|12@1+ (0.1,0) [0|409.5] "V"  PC
 SG_ S2P_Detail_UCSC7_39 : 12|12@1+ (0.1,0) [0|409.5] "V"  PC
 SG_ S2P_Detail_UCSC8_39 : 24|12@1+ (0.1,0) [0|409.5] "V"  PC
 SG_ S2P_Detail_Reserved_39 : 36|28@1+ (1,0) [0|268435455] ""  PC

BO_ 2400775784 S2P_Detail_UCSC2__40: 8 SBMU
 SG_ S2P_Detail_UCSC6_40 : 0|12@1+ (0.1,0) [0|409.5] "V"  PC
 SG_ S2P_Detail_UCSC7_40 : 12|12@1+ (0.1,0) [0|409.5] "V"  PC
 SG_ S2P_Detail_UCSC8_40 : 24|12@1+ (0.1,0) [0|409.5] "V"  PC
 SG_ S2P_Detail_Reserved_40 : 36|28@1+ (1,0) [0|268435455] ""  PC

BO_ 2400775785 S2P_Detail_UCSC2__41: 8 SBMU
 SG_ S2P_Detail_UCSC6_41 : 0|12@1+ (0.1,0) [0|409.5] "V"  PC
 SG_ S2P_Detail_UCSC7_41 : 12|12@1+ (0.1,0) [0|409.5] "V"  PC
 SG_ S2P_Detail_UCSC8_41 : 24|12@1+ (0.1,0) [0|409.5] "V"  PC
 SG_ S2P_Detail_Reserved_41 : 36|28@1+ (1,0) [0|268435455] ""  PC

BO_ 2400775786 S2P_Detail_UCSC2__42: 8 SBMU
 SG_ S2P_Detail_UCSC6_42 : 0|12@1+ (0.1,0) [0|409.5] "V"  PC
 SG_ S2P_Detail_UCSC7_42 : 12|12@1+ (0.1,0) [0|409.5] "V"  PC
 SG_ S2P_Detail_UCSC8_42 : 24|12@1+ (0.1,0) [0|409.5] "V"  PC
 SG_ S2P_Detail_Reserved_42 : 36|28@1+ (1,0) [0|268435455] ""  PC

BO_ 2400775787 S2P_Detail_UCSC2__43: 8 SBMU
 SG_ S2P_Detail_UCSC6_43 : 0|12@1+ (0.1,0) [0|409.5] "V"  PC
 SG_ S2P_Detail_UCSC7_43 : 12|12@1+ (0.1,0) [0|409.5] "V"  PC
 SG_ S2P_Detail_UCSC8_43 : 24|12@1+ (0.1,0) [0|409.5] "V"  PC
 SG_ S2P_Detail_Reserved_43 : 36|28@1+ (1,0) [0|268435455] ""  PC

BO_ 2400775788 S2P_Detail_UCSC2__44: 8 SBMU
 SG_ S2P_Detail_UCSC6_44 : 0|12@1+ (0.1,0) [0|409.5] "V"  PC
 SG_ S2P_Detail_UCSC7_44 : 12|12@1+ (0.1,0) [0|409.5] "V"  PC
 SG_ S2P_Detail_UCSC8_44 : 24|12@1+ (0.1,0) [0|409.5] "V"  PC
 SG_ S2P_Detail_Reserved_44 : 36|28@1+ (1,0) [0|268435455] ""  PC

BO_ 2400775789 S2P_Detail_UCSC2__45: 8 SBMU
 SG_ S2P_Detail_UCSC6_45 : 0|12@1+ (0.1,0) [0|409.5] "V"  PC
 SG_ S2P_Detail_UCSC7_45 : 12|12@1+ (0.1,0) [0|409.5] "V"  PC
 SG_ S2P_Detail_UCSC8_45 : 24|12@1+ (0.1,0) [0|409.5] "V"  PC
 SG_ S2P_Detail_Reserved_45 : 36|28@1+ (1,0) [0|268435455] ""  PC

BO_ 2400775790 S2P_Detail_UCSC2__46: 8 SBMU
 SG_ S2P_Detail_UCSC6_46 : 0|12@1+ (0.1,0) [0|409.5] "V"  PC
 SG_ S2P_Detail_UCSC7_46 : 12|12@1+ (0.1,0) [0|409.5] "V"  PC
 SG_ S2P_Detail_UCSC8_46 : 24|12@1+ (0.1,0) [0|409.5] "V"  PC
 SG_ S2P_Detail_Reserved_46 : 36|28@1+ (1,0) [0|268435455] ""  PC

BO_ 2400775791 S2P_Detail_UCSC2__47: 8 SBMU
 SG_ S2P_Detail_UCSC6_47 : 0|12@1+ (0.1,0) [0|409.5] "V"  PC
 SG_ S2P_Detail_UCSC7_47 : 12|12@1+ (0.1,0) [0|409.5] "V"  PC
 SG_ S2P_Detail_UCSC8_47 : 24|12@1+ (0.1,0) [0|409.5] "V"  PC
 SG_ S2P_Detail_Reserved_47 : 36|28@1+ (1,0) [0|268435455] ""  PC

BO_ 2400775792 S2P_Detail_UCSC2__48: 8 SBMU
 SG_ S2P_Detail_UCSC6_48 : 0|12@1+ (0.1,0) [0|409.5] "V"  PC
 SG_ S2P_Detail_UCSC7_48 : 12|12@1+ (0.1,0) [0|409.5] "V"  PC
 SG_ S2P_Detail_UCSC8_48 : 24|12@1+ (0.1,0) [0|409.5] "V"  PC
 SG_ S2P_Detail_Reserved_48 : 36|28@1+ (1,0) [0|268435455] ""  PC

BO_ 2400775793 S2P_Detail_UCSC2__49: 8 SBMU
 SG_ S2P_Detail_UCSC6_49 : 0|12@1+ (0.1,0) [0|409.5] "V"  PC
 SG_ S2P_Detail_UCSC7_49 : 12|12@1+ (0.1,0) [0|409.5] "V"  PC
 SG_ S2P_Detail_UCSC8_49 : 24|12@1+ (0.1,0) [0|409.5] "V"  PC
 SG_ S2P_Detail_Reserved_49 : 36|28@1+ (1,0) [0|268435455] ""  PC

BO_ 2400775794 S2P_Detail_UCSC2__50: 8 SBMU
 SG_ S2P_Detail_UCSC6_50 : 0|12@1+ (0.1,0) [0|409.5] "V"  PC
 SG_ S2P_Detail_UCSC7_50 : 12|12@1+ (0.1,0) [0|409.5] "V"  PC
 SG_ S2P_Detail_UCSC8_50 : 24|12@1+ (0.1,0) [0|409.5] "V"  PC
 SG_ S2P_Detail_Reserved_50 : 36|28@1+ (1,0) [0|268435455] ""  PC

BO_ 2400775795 S2P_Detail_UCSC2__51: 8 SBMU
 SG_ S2P_Detail_UCSC6_51 : 0|12@1+ (0.1,0) [0|409.5] "V"  PC
 SG_ S2P_Detail_UCSC7_51 : 12|12@1+ (0.1,0) [0|409.5] "V"  PC
 SG_ S2P_Detail_UCSC8_51 : 24|12@1+ (0.1,0) [0|409.5] "V"  PC
 SG_ S2P_Detail_Reserved_51 : 36|28@1+ (1,0) [0|268435455] ""  PC

BO_ 2400775796 S2P_Detail_UCSC2__52: 8 SBMU
 SG_ S2P_Detail_UCSC6_52 : 0|12@1+ (0.1,0) [0|409.5] "V"  PC
 SG_ S2P_Detail_UCSC7_52 : 12|12@1+ (0.1,0) [0|409.5] "V"  PC
 SG_ S2P_Detail_UCSC8_52 : 24|12@1+ (0.1,0) [0|409.5] "V"  PC
 SG_ S2P_Detail_Reserved_52 : 36|28@1+ (1,0) [0|268435455] ""  PC

BO_ 2400775797 S2P_Detail_UCSC2__53: 8 SBMU
 SG_ S2P_Detail_UCSC6_53 : 0|12@1+ (0.1,0) [0|409.5] "V"  PC
 SG_ S2P_Detail_UCSC7_53 : 12|12@1+ (0.1,0) [0|409.5] "V"  PC
 SG_ S2P_Detail_UCSC8_53 : 24|12@1+ (0.1,0) [0|409.5] "V"  PC
 SG_ S2P_Detail_Reserved_53 : 36|28@1+ (1,0) [0|268435455] ""  PC

BO_ 2400775798 S2P_Detail_UCSC2__54: 8 SBMU
 SG_ S2P_Detail_UCSC6_54 : 0|12@1+ (0.1,0) [0|409.5] "V"  PC
 SG_ S2P_Detail_UCSC7_54 : 12|12@1+ (0.1,0) [0|409.5] "V"  PC
 SG_ S2P_Detail_UCSC8_54 : 24|12@1+ (0.1,0) [0|409.5] "V"  PC
 SG_ S2P_Detail_Reserved_54 : 36|28@1+ (1,0) [0|268435455] ""  PC

BO_ 2400775799 S2P_Detail_UCSC2__55: 8 SBMU
 SG_ S2P_Detail_UCSC6_55 : 0|12@1+ (0.1,0) [0|409.5] "V"  PC
 SG_ S2P_Detail_UCSC7_55 : 12|12@1+ (0.1,0) [0|409.5] "V"  PC
 SG_ S2P_Detail_UCSC8_55 : 24|12@1+ (0.1,0) [0|409.5] "V"  PC
 SG_ S2P_Detail_Reserved_55 : 36|28@1+ (1,0) [0|268435455] ""  PC

BO_ 2400775800 S2P_Detail_UCSC2__56: 8 SBMU
 SG_ S2P_Detail_UCSC6_56 : 0|12@1+ (0.1,0) [0|409.5] "V"  PC
 SG_ S2P_Detail_UCSC7_56 : 12|12@1+ (0.1,0) [0|409.5] "V"  PC
 SG_ S2P_Detail_UCSC8_56 : 24|12@1+ (0.1,0) [0|409.5] "V"  PC
 SG_ S2P_Detail_Reserved_56 : 36|28@1+ (1,0) [0|268435455] ""  PC

BO_ 2400775801 S2P_Detail_UCSC2__57: 8 SBMU
 SG_ S2P_Detail_UCSC6_57 : 0|12@1+ (0.1,0) [0|409.5] "V"  PC
 SG_ S2P_Detail_UCSC7_57 : 12|12@1+ (0.1,0) [0|409.5] "V"  PC
 SG_ S2P_Detail_UCSC8_57 : 24|12@1+ (0.1,0) [0|409.5] "V"  PC
 SG_ S2P_Detail_Reserved_57 : 36|28@1+ (1,0) [0|268435455] ""  PC

BO_ 2400775802 S2P_Detail_UCSC2__58: 8 SBMU
 SG_ S2P_Detail_UCSC6_58 : 0|12@1+ (0.1,0) [0|409.5] "V"  PC
 SG_ S2P_Detail_UCSC7_58 : 12|12@1+ (0.1,0) [0|409.5] "V"  PC
 SG_ S2P_Detail_UCSC8_58 : 24|12@1+ (0.1,0) [0|409.5] "V"  PC
 SG_ S2P_Detail_Reserved_58 : 36|28@1+ (1,0) [0|268435455] ""  PC

BO_ 2400775803 S2P_Detail_UCSC2__59: 8 SBMU
 SG_ S2P_Detail_UCSC6_59 : 0|12@1+ (0.1,0) [0|409.5] "V"  PC
 SG_ S2P_Detail_UCSC7_59 : 12|12@1+ (0.1,0) [0|409.5] "V"  PC
 SG_ S2P_Detail_UCSC8_59 : 24|12@1+ (0.1,0) [0|409.5] "V"  PC
 SG_ S2P_Detail_Reserved_59 : 36|28@1+ (1,0) [0|268435455] ""  PC

BO_ 2400775804 S2P_Detail_UCSC2__60: 8 SBMU
 SG_ S2P_Detail_UCSC6_60 : 0|12@1+ (0.1,0) [0|409.5] "V"  PC
 SG_ S2P_Detail_UCSC7_60 : 12|12@1+ (0.1,0) [0|409.5] "V"  PC
 SG_ S2P_Detail_UCSC8_60 : 24|12@1+ (0.1,0) [0|409.5] "V"  PC
 SG_ S2P_Detail_Reserved_60 : 36|28@1+ (1,0) [0|268435455] ""  PC

BO_ 2400775805 S2P_Detail_UCSC2__61: 8 SBMU
 SG_ S2P_Detail_UCSC6_61 : 0|12@1+ (0.1,0) [0|409.5] "V"  PC
 SG_ S2P_Detail_UCSC7_61 : 12|12@1+ (0.1,0) [0|409.5] "V"  PC
 SG_ S2P_Detail_UCSC8_61 : 24|12@1+ (0.1,0) [0|409.5] "V"  PC
 SG_ S2P_Detail_Reserved_61 : 36|28@1+ (1,0) [0|268435455] ""  PC

BO_ 2400775806 S2P_Detail_UCSC2__62: 8 SBMU
 SG_ S2P_Detail_UCSC6_62 : 0|12@1+ (0.1,0) [0|409.5] "V"  PC
 SG_ S2P_Detail_UCSC7_62 : 12|12@1+ (0.1,0) [0|409.5] "V"  PC
 SG_ S2P_Detail_UCSC8_62 : 24|12@1+ (0.1,0) [0|409.5] "V"  PC
 SG_ S2P_Detail_Reserved_62 : 36|28@1+ (1,0) [0|268435455] ""  PC

BO_ 2400775807 S2P_Detail_UCSC2__63: 8 SBMU
 SG_ S2P_Detail_UCSC6_63 : 0|12@1+ (0.1,0) [0|409.5] "V"  PC
 SG_ S2P_Detail_UCSC7_63 : 12|12@1+ (0.1,0) [0|409.5] "V"  PC
 SG_ S2P_Detail_UCSC8_63 : 24|12@1+ (0.1,0) [0|409.5] "V"  PC
 SG_ S2P_Detail_Reserved_63 : 36|28@1+ (1,0) [0|268435455] ""  PC

BO_ 2333208209 M2P_SUMDATA1_CUS__01: 8 MBMU
 SG_ M2P_SUMDATA1_CUS_Reserved1_01 : 0|64@1+ (1,0) [0|1.84467440737096E+019] ""  PC

BO_ 2333208210 M2P_SUMDATA1_CUS__02: 8 MBMU
 SG_ M2P_SUMDATA1_CUS_Reserved1_02 : 0|64@1+ (1,0) [0|1.84467440737096E+019] ""  PC

BO_ 2333208211 M2P_SUMDATA1_CUS__03: 8 MBMU
 SG_ M2P_SUMDATA1_CUS_Reserved1_03 : 0|64@1+ (1,0) [0|1.84467440737096E+019] ""  PC

BO_ 2333208212 M2P_SUMDATA1_CUS__04: 8 MBMU
 SG_ M2P_SUMDATA1_CUS_Reserved1_04 : 0|64@1+ (1,0) [0|1.84467440737096E+019] ""  PC

BO_ 2333208213 M2P_SUMDATA1_CUS__05: 8 MBMU
 SG_ M2P_SUMDATA1_CUS_Reserved1_05 : 0|64@1+ (1,0) [0|1.84467440737096E+019] ""  PC

BO_ 2333208214 M2P_SUMDATA1_CUS__06: 8 MBMU
 SG_ M2P_SUMDATA1_CUS_Reserved1_06 : 0|64@1+ (1,0) [0|1.84467440737096E+019] ""  PC

BO_ 2333208215 M2P_SUMDATA1_CUS__07: 8 MBMU
 SG_ M2P_SUMDATA1_CUS_Reserved1_07 : 0|64@1+ (1,0) [0|1.84467440737096E+019] ""  PC

BO_ 2333208216 M2P_SUMDATA1_CUS__08: 8 MBMU
 SG_ M2P_SUMDATA1_CUS_Reserved1_08 : 0|64@1+ (1,0) [0|1.84467440737096E+019] ""  PC

BO_ 2333208217 M2P_SUMDATA1_CUS__09: 8 MBMU
 SG_ M2P_SUMDATA1_CUS_Reserved1_09 : 0|64@1+ (1,0) [0|1.84467440737096E+019] ""  PC

BO_ 2333208218 M2P_SUMDATA1_CUS__10: 8 MBMU
 SG_ M2P_SUMDATA1_CUS_Reserved1_10 : 0|64@1+ (1,0) [0|1.84467440737096E+019] ""  PC

BO_ 2333208219 M2P_SUMDATA1_CUS__11: 8 MBMU
 SG_ M2P_SUMDATA1_CUS_Reserved1_11 : 0|64@1+ (1,0) [0|1.84467440737096E+019] ""  PC

BO_ 2333208220 M2P_SUMDATA1_CUS__12: 8 MBMU
 SG_ M2P_SUMDATA1_CUS_Reserved1_12 : 0|64@1+ (1,0) [0|1.84467440737096E+019] ""  PC

BO_ 2333208221 M2P_SUMDATA1_CUS__13: 8 MBMU
 SG_ M2P_SUMDATA1_CUS_Reserved1_13 : 0|64@1+ (1,0) [0|1.84467440737096E+019] ""  PC

BO_ 2333208222 M2P_SUMDATA1_CUS__14: 8 MBMU
 SG_ M2P_SUMDATA1_CUS_Reserved1_14 : 0|64@1+ (1,0) [0|1.84467440737096E+019] ""  PC

BO_ 2333208223 M2P_SUMDATA1_CUS__15: 8 MBMU
 SG_ M2P_SUMDATA1_CUS_Reserved1_15 : 0|64@1+ (1,0) [0|1.84467440737096E+019] ""  PC

BO_ 2333208224 M2P_SUMDATA1_CUS__16: 8 MBMU
 SG_ M2P_SUMDATA1_CUS_Reserved1_16 : 0|64@1+ (1,0) [0|1.84467440737096E+019] ""  PC

BO_ 2333208225 M2P_SUMDATA1_CUS__17: 8 MBMU
 SG_ M2P_SUMDATA1_CUS_Reserved1_17 : 0|64@1+ (1,0) [0|1.84467440737096E+019] ""  PC

BO_ 2333208226 M2P_SUMDATA1_CUS__18: 8 MBMU
 SG_ M2P_SUMDATA1_CUS_Reserved1_18 : 0|64@1+ (1,0) [0|1.84467440737096E+019] ""  PC

BO_ 2333208227 M2P_SUMDATA1_CUS__19: 8 MBMU
 SG_ M2P_SUMDATA1_CUS_Reserved1_19 : 0|64@1+ (1,0) [0|1.84467440737096E+019] ""  PC

BO_ 2333208228 M2P_SUMDATA1_CUS__20: 8 MBMU
 SG_ M2P_SUMDATA1_CUS_Reserved1_20 : 0|64@1+ (1,0) [0|1.84467440737096E+019] ""  PC

BO_ 2333208229 M2P_SUMDATA1_CUS__21: 8 MBMU
 SG_ M2P_SUMDATA1_CUS_Reserved1_21 : 0|64@1+ (1,0) [0|1.84467440737096E+019] ""  PC

BO_ 2333208230 M2P_SUMDATA1_CUS__22: 8 MBMU
 SG_ M2P_SUMDATA1_CUS_Reserved1_22 : 0|64@1+ (1,0) [0|1.84467440737096E+019] ""  PC

BO_ 2333208231 M2P_SUMDATA1_CUS__23: 8 MBMU
 SG_ M2P_SUMDATA1_CUS_Reserved1_23 : 0|64@1+ (1,0) [0|1.84467440737096E+019] ""  PC

BO_ 2333208232 M2P_SUMDATA1_CUS__24: 8 MBMU
 SG_ M2P_SUMDATA1_CUS_Reserved1_24 : 0|64@1+ (1,0) [0|1.84467440737096E+019] ""  PC

BO_ 2333208233 M2P_SUMDATA1_CUS__25: 8 MBMU
 SG_ M2P_SUMDATA1_CUS_Reserved1_25 : 0|64@1+ (1,0) [0|1.84467440737096E+019] ""  PC

BO_ 2333208234 M2P_SUMDATA1_CUS__26: 8 MBMU
 SG_ M2P_SUMDATA1_CUS_Reserved1_26 : 0|64@1+ (1,0) [0|1.84467440737096E+019] ""  PC

BO_ 2333208235 M2P_SUMDATA1_CUS__27: 8 MBMU
 SG_ M2P_SUMDATA1_CUS_Reserved1_27 : 0|64@1+ (1,0) [0|1.84467440737096E+019] ""  PC

BO_ 2333208236 M2P_SUMDATA1_CUS__28: 8 MBMU
 SG_ M2P_SUMDATA1_CUS_Reserved1_28 : 0|64@1+ (1,0) [0|1.84467440737096E+019] ""  PC

BO_ 2333208237 M2P_SUMDATA1_CUS__29: 8 MBMU
 SG_ M2P_SUMDATA1_CUS_Reserved1_29 : 0|64@1+ (1,0) [0|1.84467440737096E+019] ""  PC

BO_ 2333208238 M2P_SUMDATA1_CUS__30: 8 MBMU
 SG_ M2P_SUMDATA1_CUS_Reserved1_30 : 0|64@1+ (1,0) [0|1.84467440737096E+019] ""  PC

BO_ 2333208239 M2P_SUMDATA1_CUS__31: 8 MBMU
 SG_ M2P_SUMDATA1_CUS_Reserved1_31 : 0|64@1+ (1,0) [0|1.84467440737096E+019] ""  PC

BO_ 2333273745 M2P_SUMDATA2_CUS__01: 8 MBMU
 SG_ M2P_SUMDATA2_CUS_Reserved2_01 : 0|64@1+ (1,0) [0|1.84467440737096E+019] ""  PC

BO_ 2333273746 M2P_SUMDATA2_CUS__02: 8 MBMU
 SG_ M2P_SUMDATA2_CUS_Reserved2_02 : 0|64@1+ (1,0) [0|1.84467440737096E+019] ""  PC

BO_ 2333273747 M2P_SUMDATA2_CUS__03: 8 MBMU
 SG_ M2P_SUMDATA2_CUS_Reserved2_03 : 0|64@1+ (1,0) [0|1.84467440737096E+019] ""  PC

BO_ 2333273748 M2P_SUMDATA2_CUS__04: 8 MBMU
 SG_ M2P_SUMDATA2_CUS_Reserved2_04 : 0|64@1+ (1,0) [0|1.84467440737096E+019] ""  PC

BO_ 2333273749 M2P_SUMDATA2_CUS__05: 8 MBMU
 SG_ M2P_SUMDATA2_CUS_Reserved2_05 : 0|64@1+ (1,0) [0|1.84467440737096E+019] ""  PC

BO_ 2333273750 M2P_SUMDATA2_CUS__06: 8 MBMU
 SG_ M2P_SUMDATA2_CUS_Reserved2_06 : 0|64@1+ (1,0) [0|1.84467440737096E+019] ""  PC

BO_ 2333273751 M2P_SUMDATA2_CUS__07: 8 MBMU
 SG_ M2P_SUMDATA2_CUS_Reserved2_07 : 0|64@1+ (1,0) [0|1.84467440737096E+019] ""  PC

BO_ 2333273752 M2P_SUMDATA2_CUS__08: 8 MBMU
 SG_ M2P_SUMDATA2_CUS_Reserved2_08 : 0|64@1+ (1,0) [0|1.84467440737096E+019] ""  PC

BO_ 2333273753 M2P_SUMDATA2_CUS__09: 8 MBMU
 SG_ M2P_SUMDATA2_CUS_Reserved2_09 : 0|64@1+ (1,0) [0|1.84467440737096E+019] ""  PC

BO_ 2333273754 M2P_SUMDATA2_CUS__10: 8 MBMU
 SG_ M2P_SUMDATA2_CUS_Reserved2_10 : 0|64@1+ (1,0) [0|1.84467440737096E+019] ""  PC

BO_ 2333273755 M2P_SUMDATA2_CUS__11: 8 MBMU
 SG_ M2P_SUMDATA2_CUS_Reserved2_11 : 0|64@1+ (1,0) [0|1.84467440737096E+019] ""  PC

BO_ 2333273756 M2P_SUMDATA2_CUS__12: 8 MBMU
 SG_ M2P_SUMDATA2_CUS_Reserved2_12 : 0|64@1+ (1,0) [0|1.84467440737096E+019] ""  PC

BO_ 2333273757 M2P_SUMDATA2_CUS__13: 8 MBMU
 SG_ M2P_SUMDATA2_CUS_Reserved2_13 : 0|64@1+ (1,0) [0|1.84467440737096E+019] ""  PC

BO_ 2333273758 M2P_SUMDATA2_CUS__14: 8 MBMU
 SG_ M2P_SUMDATA2_CUS_Reserved2_14 : 0|64@1+ (1,0) [0|1.84467440737096E+019] ""  PC

BO_ 2333273759 M2P_SUMDATA2_CUS__15: 8 MBMU
 SG_ M2P_SUMDATA2_CUS_Reserved2_15 : 0|64@1+ (1,0) [0|1.84467440737096E+019] ""  PC

BO_ 2333273760 M2P_SUMDATA2_CUS__16: 8 MBMU
 SG_ M2P_SUMDATA2_CUS_Reserved2_16 : 0|64@1+ (1,0) [0|1.84467440737096E+019] ""  PC

BO_ 2333273761 M2P_SUMDATA2_CUS__17: 8 MBMU
 SG_ M2P_SUMDATA2_CUS_Reserved2_17 : 0|64@1+ (1,0) [0|1.84467440737096E+019] ""  PC

BO_ 2333273762 M2P_SUMDATA2_CUS__18: 8 MBMU
 SG_ M2P_SUMDATA2_CUS_Reserved2_18 : 0|64@1+ (1,0) [0|1.84467440737096E+019] ""  PC

BO_ 2333273763 M2P_SUMDATA2_CUS__19: 8 MBMU
 SG_ M2P_SUMDATA2_CUS_Reserved2_19 : 0|64@1+ (1,0) [0|1.84467440737096E+019] ""  PC

BO_ 2333273764 M2P_SUMDATA2_CUS__20: 8 MBMU
 SG_ M2P_SUMDATA2_CUS_Reserved2_20 : 0|64@1+ (1,0) [0|1.84467440737096E+019] ""  PC

BO_ 2333273765 M2P_SUMDATA2_CUS__21: 8 MBMU
 SG_ M2P_SUMDATA2_CUS_Reserved2_21 : 0|64@1+ (1,0) [0|1.84467440737096E+019] ""  PC

BO_ 2333273766 M2P_SUMDATA2_CUS__22: 8 MBMU
 SG_ M2P_SUMDATA2_CUS_Reserved2_22 : 0|64@1+ (1,0) [0|1.84467440737096E+019] ""  PC

BO_ 2333273767 M2P_SUMDATA2_CUS__23: 8 MBMU
 SG_ M2P_SUMDATA2_CUS_Reserved2_23 : 0|64@1+ (1,0) [0|1.84467440737096E+019] ""  PC

BO_ 2333273768 M2P_SUMDATA2_CUS__24: 8 MBMU
 SG_ M2P_SUMDATA2_CUS_Reserved2_24 : 0|64@1+ (1,0) [0|1.84467440737096E+019] ""  PC

BO_ 2333273769 M2P_SUMDATA2_CUS__25: 8 MBMU
 SG_ M2P_SUMDATA2_CUS_Reserved2_25 : 0|64@1+ (1,0) [0|1.84467440737096E+019] ""  PC

BO_ 2333273770 M2P_SUMDATA2_CUS__26: 8 MBMU
 SG_ M2P_SUMDATA2_CUS_Reserved2_26 : 0|64@1+ (1,0) [0|1.84467440737096E+019] ""  PC

BO_ 2333273771 M2P_SUMDATA2_CUS__27: 8 MBMU
 SG_ M2P_SUMDATA2_CUS_Reserved2_27 : 0|64@1+ (1,0) [0|1.84467440737096E+019] ""  PC

BO_ 2333273772 M2P_SUMDATA2_CUS__28: 8 MBMU
 SG_ M2P_SUMDATA2_CUS_Reserved2_28 : 0|64@1+ (1,0) [0|1.84467440737096E+019] ""  PC

BO_ 2333273773 M2P_SUMDATA2_CUS__29: 8 MBMU
 SG_ M2P_SUMDATA2_CUS_Reserved2_29 : 0|64@1+ (1,0) [0|1.84467440737096E+019] ""  PC

BO_ 2333273774 M2P_SUMDATA2_CUS__30: 8 MBMU
 SG_ M2P_SUMDATA2_CUS_Reserved2_30 : 0|64@1+ (1,0) [0|1.84467440737096E+019] ""  PC

BO_ 2333273775 M2P_SUMDATA2_CUS__31: 8 MBMU
 SG_ M2P_SUMDATA2_CUS_Reserved2_31 : 0|64@1+ (1,0) [0|1.84467440737096E+019] ""  PC

BO_ 2333339281 M2P_SUMDATA3_CUS__01: 8 MBMU
 SG_ M2P_SUMDATA3_CUS_Reserved3_01 : 0|64@1+ (1,0) [0|1.84467440737096E+019] ""  PC

BO_ 2333339282 M2P_SUMDATA3_CUS__02: 8 MBMU
 SG_ M2P_SUMDATA3_CUS_Reserved3_02 : 0|64@1+ (1,0) [0|1.84467440737096E+019] ""  PC

BO_ 2333339283 M2P_SUMDATA3_CUS__03: 8 MBMU
 SG_ M2P_SUMDATA3_CUS_Reserved3_03 : 0|64@1+ (1,0) [0|1.84467440737096E+019] ""  PC

BO_ 2333339284 M2P_SUMDATA3_CUS__04: 8 MBMU
 SG_ M2P_SUMDATA3_CUS_Reserved3_04 : 0|64@1+ (1,0) [0|1.84467440737096E+019] ""  PC

BO_ 2333339285 M2P_SUMDATA3_CUS__05: 8 MBMU
 SG_ M2P_SUMDATA3_CUS_Reserved3_05 : 0|64@1+ (1,0) [0|1.84467440737096E+019] ""  PC

BO_ 2333339286 M2P_SUMDATA3_CUS__06: 8 MBMU
 SG_ M2P_SUMDATA3_CUS_Reserved3_06 : 0|64@1+ (1,0) [0|1.84467440737096E+019] ""  PC

BO_ 2333339287 M2P_SUMDATA3_CUS__07: 8 MBMU
 SG_ M2P_SUMDATA3_CUS_Reserved3_07 : 0|64@1+ (1,0) [0|1.84467440737096E+019] ""  PC

BO_ 2333339288 M2P_SUMDATA3_CUS__08: 8 MBMU
 SG_ M2P_SUMDATA3_CUS_Reserved3_08 : 0|64@1+ (1,0) [0|1.84467440737096E+019] ""  PC

BO_ 2333339289 M2P_SUMDATA3_CUS__09: 8 MBMU
 SG_ M2P_SUMDATA3_CUS_Reserved3_09 : 0|64@1+ (1,0) [0|1.84467440737096E+019] ""  PC

BO_ 2333339290 M2P_SUMDATA3_CUS__10: 8 MBMU
 SG_ M2P_SUMDATA3_CUS_Reserved3_10 : 0|64@1+ (1,0) [0|1.84467440737096E+019] ""  PC

BO_ 2333339291 M2P_SUMDATA3_CUS__11: 8 MBMU
 SG_ M2P_SUMDATA3_CUS_Reserved3_11 : 0|64@1+ (1,0) [0|1.84467440737096E+019] ""  PC

BO_ 2333339292 M2P_SUMDATA3_CUS__12: 8 MBMU
 SG_ M2P_SUMDATA3_CUS_Reserved3_12 : 0|64@1+ (1,0) [0|1.84467440737096E+019] ""  PC

BO_ 2333339293 M2P_SUMDATA3_CUS__13: 8 MBMU
 SG_ M2P_SUMDATA3_CUS_Reserved3_13 : 0|64@1+ (1,0) [0|1.84467440737096E+019] ""  PC

BO_ 2333339294 M2P_SUMDATA3_CUS__14: 8 MBMU
 SG_ M2P_SUMDATA3_CUS_Reserved3_14 : 0|64@1+ (1,0) [0|1.84467440737096E+019] ""  PC

BO_ 2333339295 M2P_SUMDATA3_CUS__15: 8 MBMU
 SG_ M2P_SUMDATA3_CUS_Reserved3_15 : 0|64@1+ (1,0) [0|1.84467440737096E+019] ""  PC

BO_ 2333339296 M2P_SUMDATA3_CUS__16: 8 MBMU
 SG_ M2P_SUMDATA3_CUS_Reserved3_16 : 0|64@1+ (1,0) [0|1.84467440737096E+019] ""  PC

BO_ 2333339297 M2P_SUMDATA3_CUS__17: 8 MBMU
 SG_ M2P_SUMDATA3_CUS_Reserved3_17 : 0|64@1+ (1,0) [0|1.84467440737096E+019] ""  PC

BO_ 2333339298 M2P_SUMDATA3_CUS__18: 8 MBMU
 SG_ M2P_SUMDATA3_CUS_Reserved3_18 : 0|64@1+ (1,0) [0|1.84467440737096E+019] ""  PC

BO_ 2333339299 M2P_SUMDATA3_CUS__19: 8 MBMU
 SG_ M2P_SUMDATA3_CUS_Reserved3_19 : 0|64@1+ (1,0) [0|1.84467440737096E+019] ""  PC

BO_ 2333339300 M2P_SUMDATA3_CUS__20: 8 MBMU
 SG_ M2P_SUMDATA3_CUS_Reserved3_20 : 0|64@1+ (1,0) [0|1.84467440737096E+019] ""  PC

BO_ 2333339301 M2P_SUMDATA3_CUS__21: 8 MBMU
 SG_ M2P_SUMDATA3_CUS_Reserved3_21 : 0|64@1+ (1,0) [0|1.84467440737096E+019] ""  PC

BO_ 2333339302 M2P_SUMDATA3_CUS__22: 8 MBMU
 SG_ M2P_SUMDATA3_CUS_Reserved3_22 : 0|64@1+ (1,0) [0|1.84467440737096E+019] ""  PC

BO_ 2333339303 M2P_SUMDATA3_CUS__23: 8 MBMU
 SG_ M2P_SUMDATA3_CUS_Reserved3_23 : 0|64@1+ (1,0) [0|1.84467440737096E+019] ""  PC

BO_ 2333339304 M2P_SUMDATA3_CUS__24: 8 MBMU
 SG_ M2P_SUMDATA3_CUS_Reserved3_24 : 0|64@1+ (1,0) [0|1.84467440737096E+019] ""  PC

BO_ 2333339305 M2P_SUMDATA3_CUS__25: 8 MBMU
 SG_ M2P_SUMDATA3_CUS_Reserved3_25 : 0|64@1+ (1,0) [0|1.84467440737096E+019] ""  PC

BO_ 2333339306 M2P_SUMDATA3_CUS__26: 8 MBMU
 SG_ M2P_SUMDATA3_CUS_Reserved3_26 : 0|64@1+ (1,0) [0|1.84467440737096E+019] ""  PC

BO_ 2333339307 M2P_SUMDATA3_CUS__27: 8 MBMU
 SG_ M2P_SUMDATA3_CUS_Reserved3_27 : 0|64@1+ (1,0) [0|1.84467440737096E+019] ""  PC

BO_ 2333339308 M2P_SUMDATA3_CUS__28: 8 MBMU
 SG_ M2P_SUMDATA3_CUS_Reserved3_28 : 0|64@1+ (1,0) [0|1.84467440737096E+019] ""  PC

BO_ 2333339309 M2P_SUMDATA3_CUS__29: 8 MBMU
 SG_ M2P_SUMDATA3_CUS_Reserved3_29 : 0|64@1+ (1,0) [0|1.84467440737096E+019] ""  PC

BO_ 2333339310 M2P_SUMDATA3_CUS__30: 8 MBMU
 SG_ M2P_SUMDATA3_CUS_Reserved3_30 : 0|64@1+ (1,0) [0|1.84467440737096E+019] ""  PC

BO_ 2333339311 M2P_SUMDATA3_CUS__31: 8 MBMU
 SG_ M2P_SUMDATA3_CUS_Reserved3_31 : 0|64@1+ (1,0) [0|1.84467440737096E+019] ""  PC

BO_ 2333404817 M2P_SUMDATA4_CUS__01: 8 MBMU
 SG_ M2P_SUMDATA4_CUS_Reserved4_01 : 0|64@1+ (1,0) [0|1.84467440737096E+019] ""  PC

BO_ 2333404818 M2P_SUMDATA4_CUS__02: 8 MBMU
 SG_ M2P_SUMDATA4_CUS_Reserved4_02 : 0|64@1+ (1,0) [0|1.84467440737096E+019] ""  PC

BO_ 2333404819 M2P_SUMDATA4_CUS__03: 8 MBMU
 SG_ M2P_SUMDATA4_CUS_Reserved4_03 : 0|64@1+ (1,0) [0|1.84467440737096E+019] ""  PC

BO_ 2333404820 M2P_SUMDATA4_CUS__04: 8 MBMU
 SG_ M2P_SUMDATA4_CUS_Reserved4_04 : 0|64@1+ (1,0) [0|1.84467440737096E+019] ""  PC

BO_ 2333404821 M2P_SUMDATA4_CUS__05: 8 MBMU
 SG_ M2P_SUMDATA4_CUS_Reserved4_05 : 0|64@1+ (1,0) [0|1.84467440737096E+019] ""  PC

BO_ 2333404822 M2P_SUMDATA4_CUS__06: 8 MBMU
 SG_ M2P_SUMDATA4_CUS_Reserved4_06 : 0|64@1+ (1,0) [0|1.84467440737096E+019] ""  PC

BO_ 2333404823 M2P_SUMDATA4_CUS__07: 8 MBMU
 SG_ M2P_SUMDATA4_CUS_Reserved4_07 : 0|64@1+ (1,0) [0|1.84467440737096E+019] ""  PC

BO_ 2333404824 M2P_SUMDATA4_CUS__08: 8 MBMU
 SG_ M2P_SUMDATA4_CUS_Reserved4_08 : 0|64@1+ (1,0) [0|1.84467440737096E+019] ""  PC

BO_ 2333404825 M2P_SUMDATA4_CUS__09: 8 MBMU
 SG_ M2P_SUMDATA4_CUS_Reserved4_09 : 0|64@1+ (1,0) [0|1.84467440737096E+019] ""  PC

BO_ 2333404826 M2P_SUMDATA4_CUS__10: 8 MBMU
 SG_ M2P_SUMDATA4_CUS_Reserved4_10 : 0|64@1+ (1,0) [0|1.84467440737096E+019] ""  PC

BO_ 2333404827 M2P_SUMDATA4_CUS__11: 8 MBMU
 SG_ M2P_SUMDATA4_CUS_Reserved4_11 : 0|64@1+ (1,0) [0|1.84467440737096E+019] ""  PC

BO_ 2333404828 M2P_SUMDATA4_CUS__12: 8 MBMU
 SG_ M2P_SUMDATA4_CUS_Reserved4_12 : 0|64@1+ (1,0) [0|1.84467440737096E+019] ""  PC

BO_ 2333404829 M2P_SUMDATA4_CUS__13: 8 MBMU
 SG_ M2P_SUMDATA4_CUS_Reserved4_13 : 0|64@1+ (1,0) [0|1.84467440737096E+019] ""  PC

BO_ 2333404830 M2P_SUMDATA4_CUS__14: 8 MBMU
 SG_ M2P_SUMDATA4_CUS_Reserved4_14 : 0|64@1+ (1,0) [0|1.84467440737096E+019] ""  PC

BO_ 2333404831 M2P_SUMDATA4_CUS__15: 8 MBMU
 SG_ M2P_SUMDATA4_CUS_Reserved4_15 : 0|64@1+ (1,0) [0|1.84467440737096E+019] ""  PC

BO_ 2333404832 M2P_SUMDATA4_CUS__16: 8 MBMU
 SG_ M2P_SUMDATA4_CUS_Reserved4_16 : 0|64@1+ (1,0) [0|1.84467440737096E+019] ""  PC

BO_ 2333404833 M2P_SUMDATA4_CUS__17: 8 MBMU
 SG_ M2P_SUMDATA4_CUS_Reserved4_17 : 0|64@1+ (1,0) [0|1.84467440737096E+019] ""  PC

BO_ 2333404834 M2P_SUMDATA4_CUS__18: 8 MBMU
 SG_ M2P_SUMDATA4_CUS_Reserved4_18 : 0|64@1+ (1,0) [0|1.84467440737096E+019] ""  PC

BO_ 2333404835 M2P_SUMDATA4_CUS__19: 8 MBMU
 SG_ M2P_SUMDATA4_CUS_Reserved4_19 : 0|64@1+ (1,0) [0|1.84467440737096E+019] ""  PC

BO_ 2333404836 M2P_SUMDATA4_CUS__20: 8 MBMU
 SG_ M2P_SUMDATA4_CUS_Reserved4_20 : 0|64@1+ (1,0) [0|1.84467440737096E+019] ""  PC

BO_ 2333404837 M2P_SUMDATA4_CUS__21: 8 MBMU
 SG_ M2P_SUMDATA4_CUS_Reserved4_21 : 0|64@1+ (1,0) [0|1.84467440737096E+019] ""  PC

BO_ 2333404838 M2P_SUMDATA4_CUS__22: 8 MBMU
 SG_ M2P_SUMDATA4_CUS_Reserved4_22 : 0|64@1+ (1,0) [0|1.84467440737096E+019] ""  PC

BO_ 2333404839 M2P_SUMDATA4_CUS__23: 8 MBMU
 SG_ M2P_SUMDATA4_CUS_Reserved4_23 : 0|64@1+ (1,0) [0|1.84467440737096E+019] ""  PC

BO_ 2333404840 M2P_SUMDATA4_CUS__24: 8 MBMU
 SG_ M2P_SUMDATA4_CUS_Reserved4_24 : 0|64@1+ (1,0) [0|1.84467440737096E+019] ""  PC

BO_ 2333404841 M2P_SUMDATA4_CUS__25: 8 MBMU
 SG_ M2P_SUMDATA4_CUS_Reserved4_25 : 0|64@1+ (1,0) [0|1.84467440737096E+019] ""  PC

BO_ 2333404842 M2P_SUMDATA4_CUS__26: 8 MBMU
 SG_ M2P_SUMDATA4_CUS_Reserved4_26 : 0|64@1+ (1,0) [0|1.84467440737096E+019] ""  PC

BO_ 2333404843 M2P_SUMDATA4_CUS__27: 8 MBMU
 SG_ M2P_SUMDATA4_CUS_Reserved4_27 : 0|64@1+ (1,0) [0|1.84467440737096E+019] ""  PC

BO_ 2333404844 M2P_SUMDATA4_CUS__28: 8 MBMU
 SG_ M2P_SUMDATA4_CUS_Reserved4_28 : 0|64@1+ (1,0) [0|1.84467440737096E+019] ""  PC

BO_ 2333404845 M2P_SUMDATA4_CUS__29: 8 MBMU
 SG_ M2P_SUMDATA4_CUS_Reserved4_29 : 0|64@1+ (1,0) [0|1.84467440737096E+019] ""  PC

BO_ 2333404846 M2P_SUMDATA4_CUS__30: 8 MBMU
 SG_ M2P_SUMDATA4_CUS_Reserved4_30 : 0|64@1+ (1,0) [0|1.84467440737096E+019] ""  PC

BO_ 2333404847 M2P_SUMDATA4_CUS__31: 8 MBMU
 SG_ M2P_SUMDATA4_CUS_Reserved4_31 : 0|64@1+ (1,0) [0|1.84467440737096E+019] ""  PC

BO_ 2333470353 M2P_SUMDATA5_CUS__01: 8 MBMU
 SG_ M2P_SUMDATA5_CUS_Reserved5_01 : 0|64@1+ (1,0) [0|1.84467440737096E+019] ""  PC

BO_ 2333470354 M2P_SUMDATA5_CUS__02: 8 MBMU
 SG_ M2P_SUMDATA5_CUS_Reserved5_02 : 0|64@1+ (1,0) [0|1.84467440737096E+019] ""  PC

BO_ 2333470355 M2P_SUMDATA5_CUS__03: 8 MBMU
 SG_ M2P_SUMDATA5_CUS_Reserved5_03 : 0|64@1+ (1,0) [0|1.84467440737096E+019] ""  PC

BO_ 2333470356 M2P_SUMDATA5_CUS__04: 8 MBMU
 SG_ M2P_SUMDATA5_CUS_Reserved5_04 : 0|64@1+ (1,0) [0|1.84467440737096E+019] ""  PC

BO_ 2333470357 M2P_SUMDATA5_CUS__05: 8 MBMU
 SG_ M2P_SUMDATA5_CUS_Reserved5_05 : 0|64@1+ (1,0) [0|1.84467440737096E+019] ""  PC

BO_ 2333470358 M2P_SUMDATA5_CUS__06: 8 MBMU
 SG_ M2P_SUMDATA5_CUS_Reserved5_06 : 0|64@1+ (1,0) [0|1.84467440737096E+019] ""  PC

BO_ 2333470359 M2P_SUMDATA5_CUS__07: 8 MBMU
 SG_ M2P_SUMDATA5_CUS_Reserved5_07 : 0|64@1+ (1,0) [0|1.84467440737096E+019] ""  PC

BO_ 2333470360 M2P_SUMDATA5_CUS__08: 8 MBMU
 SG_ M2P_SUMDATA5_CUS_Reserved5_08 : 0|64@1+ (1,0) [0|1.84467440737096E+019] ""  PC

BO_ 2333470361 M2P_SUMDATA5_CUS__09: 8 MBMU
 SG_ M2P_SUMDATA5_CUS_Reserved5_09 : 0|64@1+ (1,0) [0|1.84467440737096E+019] ""  PC

BO_ 2333470362 M2P_SUMDATA5_CUS__10: 8 MBMU
 SG_ M2P_SUMDATA5_CUS_Reserved5_10 : 0|64@1+ (1,0) [0|1.84467440737096E+019] ""  PC

BO_ 2333470363 M2P_SUMDATA5_CUS__11: 8 MBMU
 SG_ M2P_SUMDATA5_CUS_Reserved5_11 : 0|64@1+ (1,0) [0|1.84467440737096E+019] ""  PC

BO_ 2333470364 M2P_SUMDATA5_CUS__12: 8 MBMU
 SG_ M2P_SUMDATA5_CUS_Reserved5_12 : 0|64@1+ (1,0) [0|1.84467440737096E+019] ""  PC

BO_ 2333470365 M2P_SUMDATA5_CUS__13: 8 MBMU
 SG_ M2P_SUMDATA5_CUS_Reserved5_13 : 0|64@1+ (1,0) [0|1.84467440737096E+019] ""  PC

BO_ 2333470366 M2P_SUMDATA5_CUS__14: 8 MBMU
 SG_ M2P_SUMDATA5_CUS_Reserved5_14 : 0|64@1+ (1,0) [0|1.84467440737096E+019] ""  PC

BO_ 2333470367 M2P_SUMDATA5_CUS__15: 8 MBMU
 SG_ M2P_SUMDATA5_CUS_Reserved5_15 : 0|64@1+ (1,0) [0|1.84467440737096E+019] ""  PC

BO_ 2333470368 M2P_SUMDATA5_CUS__16: 8 MBMU
 SG_ M2P_SUMDATA5_CUS_Reserved5_16 : 0|64@1+ (1,0) [0|1.84467440737096E+019] ""  PC

BO_ 2333470369 M2P_SUMDATA5_CUS__17: 8 MBMU
 SG_ M2P_SUMDATA5_CUS_Reserved5_17 : 0|64@1+ (1,0) [0|1.84467440737096E+019] ""  PC

BO_ 2333470370 M2P_SUMDATA5_CUS__18: 8 MBMU
 SG_ M2P_SUMDATA5_CUS_Reserved5_18 : 0|64@1+ (1,0) [0|1.84467440737096E+019] ""  PC

BO_ 2333470371 M2P_SUMDATA5_CUS__19: 8 MBMU
 SG_ M2P_SUMDATA5_CUS_Reserved5_19 : 0|64@1+ (1,0) [0|1.84467440737096E+019] ""  PC

BO_ 2333470372 M2P_SUMDATA5_CUS__20: 8 MBMU
 SG_ M2P_SUMDATA5_CUS_Reserved5_20 : 0|64@1+ (1,0) [0|1.84467440737096E+019] ""  PC

BO_ 2333470373 M2P_SUMDATA5_CUS__21: 8 MBMU
 SG_ M2P_SUMDATA5_CUS_Reserved5_21 : 0|64@1+ (1,0) [0|1.84467440737096E+019] ""  PC

BO_ 2333470374 M2P_SUMDATA5_CUS__22: 8 MBMU
 SG_ M2P_SUMDATA5_CUS_Reserved5_22 : 0|64@1+ (1,0) [0|1.84467440737096E+019] ""  PC

BO_ 2333470375 M2P_SUMDATA5_CUS__23: 8 MBMU
 SG_ M2P_SUMDATA5_CUS_Reserved5_23 : 0|64@1+ (1,0) [0|1.84467440737096E+019] ""  PC

BO_ 2333470376 M2P_SUMDATA5_CUS__24: 8 MBMU
 SG_ M2P_SUMDATA5_CUS_Reserved5_24 : 0|64@1+ (1,0) [0|1.84467440737096E+019] ""  PC

BO_ 2333470377 M2P_SUMDATA5_CUS__25: 8 MBMU
 SG_ M2P_SUMDATA5_CUS_Reserved5_25 : 0|64@1+ (1,0) [0|1.84467440737096E+019] ""  PC

BO_ 2333470378 M2P_SUMDATA5_CUS__26: 8 MBMU
 SG_ M2P_SUMDATA5_CUS_Reserved5_26 : 0|64@1+ (1,0) [0|1.84467440737096E+019] ""  PC

BO_ 2333470379 M2P_SUMDATA5_CUS__27: 8 MBMU
 SG_ M2P_SUMDATA5_CUS_Reserved5_27 : 0|64@1+ (1,0) [0|1.84467440737096E+019] ""  PC

BO_ 2333470380 M2P_SUMDATA5_CUS__28: 8 MBMU
 SG_ M2P_SUMDATA5_CUS_Reserved5_28 : 0|64@1+ (1,0) [0|1.84467440737096E+019] ""  PC

BO_ 2333470381 M2P_SUMDATA5_CUS__29: 8 MBMU
 SG_ M2P_SUMDATA5_CUS_Reserved5_29 : 0|64@1+ (1,0) [0|1.84467440737096E+019] ""  PC

BO_ 2333470382 M2P_SUMDATA5_CUS__30: 8 MBMU
 SG_ M2P_SUMDATA5_CUS_Reserved5_30 : 0|64@1+ (1,0) [0|1.84467440737096E+019] ""  PC

BO_ 2333470383 M2P_SUMDATA5_CUS__31: 8 MBMU
 SG_ M2P_SUMDATA5_CUS_Reserved5_31 : 0|64@1+ (1,0) [0|1.84467440737096E+019] ""  PC

BO_ 2332155937 I2A_Byrack_SUMDATA1__01: 8 IMM
 SG_ I2A_Byrack_SUMDATA1_CRC_01 : 0|8@1+ (1,0) [0|255] ""  MBMU,PC
 SG_ I2A_Byrack_SUMDATA1_ALIV_01 : 8|4@1+ (1,0) [0|15] ""  MBMU,PC
 SG_ I2A_Byrack_VoltVld_01 : 12|1@1+ (1,0) [0|1] ""  MBMU,PC
 SG_ I2A_Byrack_VoltErr_01 : 13|1@1+ (1,0) [0|1] ""  MBMU,PC
 SG_ I2A_Byrack_InsResValid_01 : 14|1@1+ (1,0) [0|1] ""  MBMU,PC
 SG_ Reserved_01 : 15|1@1+ (1,0) [0|1] ""  MBMU,PC
 SG_ I2A_Byrack_IsoResPos_01 : 16|16@1+ (1,0) [0|65535] "KΩ"  MBMU,PC
 SG_ I2A_Byrack_IsoResNeg_01 : 32|16@1+ (1,0) [0|65535] "KΩ"  MBMU,PC

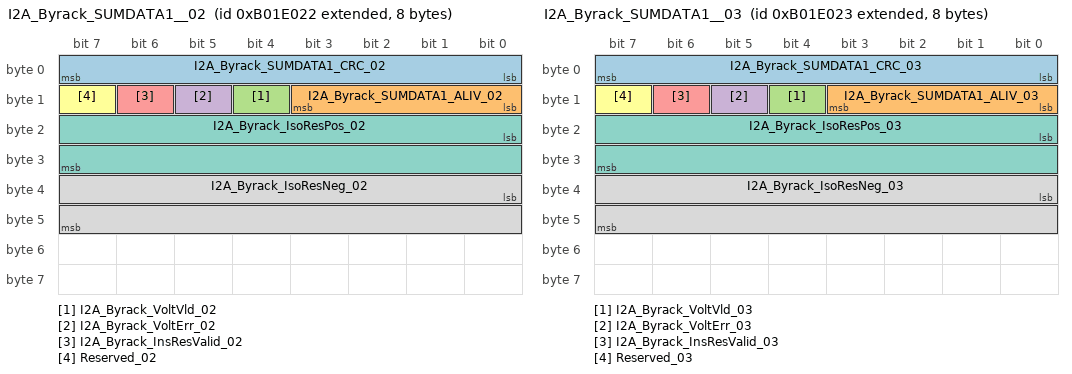
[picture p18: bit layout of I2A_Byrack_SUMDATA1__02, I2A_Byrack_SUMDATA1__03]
BO_ 2332155938 I2A_Byrack_SUMDATA1__02: 8 IMM
 SG_ I2A_Byrack_SUMDATA1_CRC_02 : 0|8@1+ (1,0) [0|255] ""  MBMU,PC
 SG_ I2A_Byrack_SUMDATA1_ALIV_02 : 8|4@1+ (1,0) [0|15] ""  MBMU,PC
 SG_ I2A_Byrack_VoltVld_02 : 12|1@1+ (1,0) [0|1] ""  MBMU,PC
 SG_ I2A_Byrack_VoltErr_02 : 13|1@1+ (1,0) [0|1] ""  MBMU,PC
 SG_ I2A_Byrack_InsResValid_02 : 14|1@1+ (1,0) [0|1] ""  MBMU,PC
 SG_ Reserved_02 : 15|1@1+ (1,0) [0|1] ""  MBMU,PC
 SG_ I2A_Byrack_IsoResPos_02 : 16|16@1+ (1,0) [0|65535] "KΩ"  MBMU,PC
 SG_ I2A_Byrack_IsoResNeg_02 : 32|16@1+ (1,0) [0|65535] "KΩ"  MBMU,PC

BO_ 2332155939 I2A_Byrack_SUMDATA1__03: 8 IMM
 SG_ I2A_Byrack_SUMDATA1_CRC_03 : 0|8@1+ (1,0) [0|255] ""  MBMU,PC
 SG_ I2A_Byrack_SUMDATA1_ALIV_03 : 8|4@1+ (1,0) [0|15] ""  MBMU,PC
 SG_ I2A_Byrack_VoltVld_03 : 12|1@1+ (1,0) [0|1] ""  MBMU,PC
 SG_ I2A_Byrack_VoltErr_03 : 13|1@1+ (1,0) [0|1] ""  MBMU,PC
 SG_ I2A_Byrack_InsResValid_03 : 14|1@1+ (1,0) [0|1] ""  MBMU,PC
 SG_ Reserved_03 : 15|1@1+ (1,0) [0|1] ""  MBMU,PC
 SG_ I2A_Byrack_IsoResPos_03 : 16|16@1+ (1,0) [0|65535] "KΩ"  MBMU,PC
 SG_ I2A_Byrack_IsoResNeg_03 : 32|16@1+ (1,0) [0|65535] "KΩ"  MBMU,PC

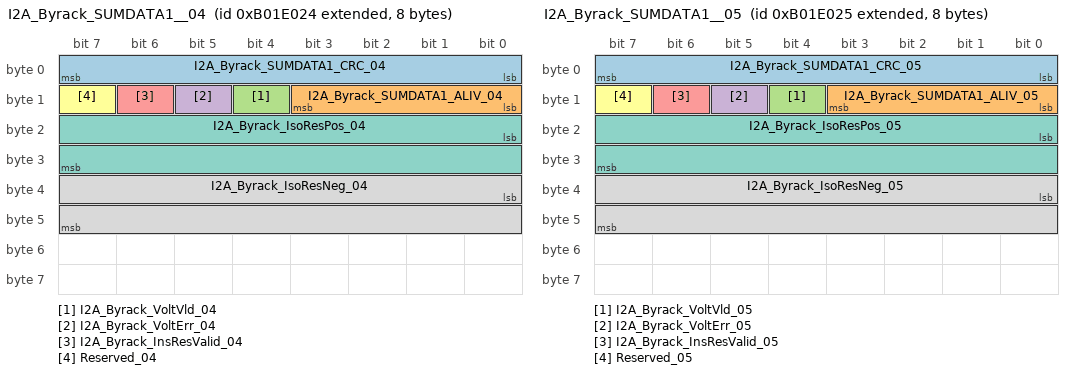
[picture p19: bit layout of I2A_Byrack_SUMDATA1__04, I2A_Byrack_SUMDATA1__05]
BO_ 2332155940 I2A_Byrack_SUMDATA1__04: 8 IMM
 SG_ I2A_Byrack_SUMDATA1_CRC_04 : 0|8@1+ (1,0) [0|255] ""  MBMU,PC
 SG_ I2A_Byrack_SUMDATA1_ALIV_04 : 8|4@1+ (1,0) [0|15] ""  MBMU,PC
 SG_ I2A_Byrack_VoltVld_04 : 12|1@1+ (1,0) [0|1] ""  MBMU,PC
 SG_ I2A_Byrack_VoltErr_04 : 13|1@1+ (1,0) [0|1] ""  MBMU,PC
 SG_ I2A_Byrack_InsResValid_04 : 14|1@1+ (1,0) [0|1] ""  MBMU,PC
 SG_ Reserved_04 : 15|1@1+ (1,0) [0|1] ""  MBMU,PC
 SG_ I2A_Byrack_IsoResPos_04 : 16|16@1+ (1,0) [0|65535] "KΩ"  MBMU,PC
 SG_ I2A_Byrack_IsoResNeg_04 : 32|16@1+ (1,0) [0|65535] "KΩ"  MBMU,PC

BO_ 2332155941 I2A_Byrack_SUMDATA1__05: 8 IMM
 SG_ I2A_Byrack_SUMDATA1_CRC_05 : 0|8@1+ (1,0) [0|255] ""  MBMU,PC
 SG_ I2A_Byrack_SUMDATA1_ALIV_05 : 8|4@1+ (1,0) [0|15] ""  MBMU,PC
 SG_ I2A_Byrack_VoltVld_05 : 12|1@1+ (1,0) [0|1] ""  MBMU,PC
 SG_ I2A_Byrack_VoltErr_05 : 13|1@1+ (1,0) [0|1] ""  MBMU,PC
 SG_ I2A_Byrack_InsResValid_05 : 14|1@1+ (1,0) [0|1] ""  MBMU,PC
 SG_ Reserved_05 : 15|1@1+ (1,0) [0|1] ""  MBMU,PC
 SG_ I2A_Byrack_IsoResPos_05 : 16|16@1+ (1,0) [0|65535] "KΩ"  MBMU,PC
 SG_ I2A_Byrack_IsoResNeg_05 : 32|16@1+ (1,0) [0|65535] "KΩ"  MBMU,PC

CM_ SG_ 2418077308 S2P_Lmt15_Over_UModule1_60 "电池模块充电电压一级报警值";
CM_ SG_ 2418077308 S2P_Lmt15_Over_RModule1_60 "电池模块充电电压一级恢复阈值";
CM_ SG_ 2418077308 S2P_Lmt15_Over_UModule2_60 "电池模块充电电压二级报警值";
CM_ SG_ 2418077308 S2P_Lmt15_Over_RModule2_60 "电池模块充电电压二级恢复阈值";
CM_ SG_ 2418077309 S2P_Lmt15_Over_UModule1_61 "电池模块充电电压一级报警值";
CM_ SG_ 2418077309 S2P_Lmt15_Over_RModule1_61 "电池模块充电电压一级恢复阈值";
CM_ SG_ 2418077309 S2P_Lmt15_Over_UModule2_61 "电池模块充电电压二级报警值";
CM_ SG_ 2418077309 S2P_Lmt15_Over_RModule2_61 "电池模块充电电压二级恢复阈值";
CM_ SG_ 2418077310 S2P_Lmt15_Over_UModule1_62 "电池模块充电电压一级报警值";
CM_ SG_ 2418077310 S2P_Lmt15_Over_RModule1_62 "电池模块充电电压一级恢复阈值";
CM_ SG_ 2418077310 S2P_Lmt15_Over_UModule2_62 "电池模块充电电压二级报警值";
CM_ SG_ 2418077310 S2P_Lmt15_Over_RModule2_62 "电池模块充电电压二级恢复阈值";
CM_ SG_ 2418077311 S2P_Lmt15_Over_UModule1_63 "电池模块充电电压一级报警值";
CM_ SG_ 2418077311 S2P_Lmt15_Over_RModule1_63 "电池模块充电电压一级恢复阈值";
CM_ SG_ 2418077311 S2P_Lmt15_Over_UModule2_63 "电池模块充电电压二级报警值";
CM_ SG_ 2418077311 S2P_Lmt15_Over_RModule2_63 "电池模块充电电压二级恢复阈值";
CM_ SG_ 2418142785 S2P_Lmt16_Under_UModule1_01 "电池模块放电电压一级报警值";
CM_ SG_ 2418142785 S2P_Lmt16_Under_RModule1_01 "电池模块放电电压一级恢复阈值";
CM_ SG_ 2418142785 S2P_Lmt16_Under_UModule2_01 "电池模块放电电压二级报警值";
CM_ SG_ 2418142785 S2P_Lmt16_Under_RModule2_01 "电池模块放电电压二级恢复阈值";
CM_ SG_ 2418142786 S2P_Lmt16_Under_UModule1_02 "电池模块放电电压一级报警值";
CM_ SG_ 2418142786 S2P_Lmt16_Under_RModule1_02 "电池模块放电电压一级恢复阈值";
CM_ SG_ 2418142786 S2P_Lmt16_Under_UModule2_02 "电池模块放电电压二级报警值";
CM_ SG_ 2418142786 S2P_Lmt16_Under_RModule2_02 "电池模块放电电压二级恢复阈值";
CM_ SG_ 2418142787 S2P_Lmt16_Under_UModule1_03 "电池模块放电电压一级报警值";
CM_ SG_ 2418142787 S2P_Lmt16_Under_RModule1_03 "电池模块放电电压一级恢复阈值";
CM_ SG_ 2418142787 S2P_Lmt16_Under_UModule2_03 "电池模块放电电压二级报警值";
CM_ SG_ 2418142787 S2P_Lmt16_Under_RModule2_03 "电池模块放电电压二级恢复阈值";
CM_ SG_ 2418142788 S2P_Lmt16_Under_UModule1_04 "电池模块放电电压一级报警值";
CM_ SG_ 2418142788 S2P_Lmt16_Under_RModule1_04 "电池模块放电电压一级恢复阈值";
CM_ SG_ 2418142788 S2P_Lmt16_Under_UModule2_04 "电池模块放电电压二级报警值";
CM_ SG_ 2418142788 S2P_Lmt16_Under_RModule2_04 "电池模块放电电压二级恢复阈值";
CM_ SG_ 2418142789 S2P_Lmt16_Under_UModule1_05 "电池模块放电电压一级报警值";
CM_ SG_ 2418142789 S2P_Lmt16_Under_RModule1_05 "电池模块放电电压一级恢复阈值";
CM_ SG_ 2418142789 S2P_Lmt16_Under_UModule2_05 "电池模块放电电压二级报警值";
CM_ SG_ 2418142789 S2P_Lmt16_Under_RModule2_05 "电池模块放电电压二级恢复阈值";
CM_ SG_ 2418142790 S2P_Lmt16_Under_UModule1_06 "电池模块放电电压一级报警值";
CM_ SG_ 2418142790 S2P_Lmt16_Under_RModule1_06 "电池模块放电电压一级恢复阈值";
CM_ SG_ 2418142790 S2P_Lmt16_Under_UModule2_06 "电池模块放电电压二级报警值";
CM_ SG_ 2418142790 S2P_Lmt16_Under_RModule2_06 "电池模块放电电压二级恢复阈值";
CM_ SG_ 2418142791 S2P_Lmt16_Under_UModule1_07 "电池模块放电电压一级报警值";
CM_ SG_ 2418142791 S2P_Lmt16_Under_RModule1_07 "电池模块放电电压一级恢复阈值";
CM_ SG_ 2418142791 S2P_Lmt16_Under_UModule2_07 "电池模块放电电压二级报警值";
CM_ SG_ 2418142791 S2P_Lmt16_Under_RModule2_07 "电池模块放电电压二级恢复阈值";
CM_ SG_ 2418142792 S2P_Lmt16_Under_UModule1_08 "电池模块放电电压一级报警值";
CM_ SG_ 2418142792 S2P_Lmt16_Under_RModule1_08 "电池模块放电电压一级恢复阈值";
CM_ SG_ 2418142792 S2P_Lmt16_Under_UModule2_08 "电池模块放电电压二级报警值";
CM_ SG_ 2418142792 S2P_Lmt16_Under_RModule2_08 "电池模块放电电压二级恢复阈值";
CM_ SG_ 2418142793 S2P_Lmt16_Under_UModule1_09 "电池模块放电电压一级报警值";
CM_ SG_ 2418142793 S2P_Lmt16_Under_RModule1_09 "电池模块放电电压一级恢复阈值";
CM_ SG_ 2418142793 S2P_Lmt16_Under_UModule2_09 "电池模块放电电压二级报警值";
CM_ SG_ 2418142793 S2P_Lmt16_Under_RModule2_09 "电池模块放电电压二级恢复阈值";
CM_ SG_ 2418142794 S2P_Lmt16_Under_UModule1_10 "电池模块放电电压一级报警值";
CM_ SG_ 2418142794 S2P_Lmt16_Under_RModule1_10 "电池模块放电电压一级恢复阈值";
CM_ SG_ 2418142794 S2P_Lmt16_Under_UModule2_10 "电池模块放电电压二级报警值";
CM_ SG_ 2418142794 S2P_Lmt16_Under_RModule2_10 "电池模块放电电压二级恢复阈值";
CM_ SG_ 2418142795 S2P_Lmt16_Under_UModule1_11 "电池模块放电电压一级报警值";
CM_ SG_ 2418142795 S2P_Lmt16_Under_RModule1_11 "电池模块放电电压一级恢复阈值";
CM_ SG_ 2418142795 S2P_Lmt16_Under_UModule2_11 "电池模块放电电压二级报警值";
CM_ SG_ 2418142795 S2P_Lmt16_Under_RModule2_11 "电池模块放电电压二级恢复阈值";
CM_ SG_ 2418142796 S2P_Lmt16_Under_UModule1_12 "电池模块放电电压一级报警值";
CM_ SG_ 2418142796 S2P_Lmt16_Under_RModule1_12 "电池模块放电电压一级恢复阈值";
CM_ SG_ 2418142796 S2P_Lmt16_Under_UModule2_12 "电池模块放电电压二级报警值";
CM_ SG_ 2418142796 S2P_Lmt16_Under_RModule2_12 "电池模块放电电压二级恢复阈值";
CM_ SG_ 2418142797 S2P_Lmt16_Under_UModule1_13 "电池模块放电电压一级报警值";
CM_ SG_ 2418142797 S2P_Lmt16_Under_RModule1_13 "电池模块放电电压一级恢复阈值";
CM_ SG_ 2418142797 S2P_Lmt16_Under_UModule2_13 "电池模块放电电压二级报警值";
CM_ SG_ 2418142797 S2P_Lmt16_Under_RModule2_13 "电池模块放电电压二级恢复阈值";
CM_ SG_ 2418142798 S2P_Lmt16_Under_UModule1_14 "电池模块放电电压一级报警值";
CM_ SG_ 2418142798 S2P_Lmt16_Under_RModule1_14 "电池模块放电电压一级恢复阈值";
CM_ SG_ 2418142798 S2P_Lmt16_Under_UModule2_14 "电池模块放电电压二级报警值";
CM_ SG_ 2418142798 S2P_Lmt16_Under_RModule2_14 "电池模块放电电压二级恢复阈值";
CM_ SG_ 2418142799 S2P_Lmt16_Under_UModule1_15 "电池模块放电电压一级报警值";
CM_ SG_ 2418142799 S2P_Lmt16_Under_RModule1_15 "电池模块放电电压一级恢复阈值";
CM_ SG_ 2418142799 S2P_Lmt16_Under_UModule2_15 "电池模块放电电压二级报警值";
CM_ SG_ 2418142799 S2P_Lmt16_Under_RModule2_15 "电池模块放电电压二级恢复阈值";
CM_ SG_ 2418142800 S2P_Lmt16_Under_UModule1_16 "电池模块放电电压一级报警值";
CM_ SG_ 2418142800 S2P_Lmt16_Under_RModule1_16 "电池模块放电电压一级恢复阈值";
CM_ SG_ 2418142800 S2P_Lmt16_Under_UModule2_16 "电池模块放电电压二级报警值";
CM_ SG_ 2418142800 S2P_Lmt16_Under_RModule2_16 "电池模块放电电压二级恢复阈值";
CM_ SG_ 2418142801 S2P_Lmt16_Under_UModule1_17 "电池模块放电电压一级报警值";
CM_ SG_ 2418142801 S2P_Lmt16_Under_RModule1_17 "电池模块放电电压一级恢复阈值";
CM_ SG_ 2418142801 S2P_Lmt16_Under_UModule2_17 "电池模块放电电压二级报警值";
CM_ SG_ 2418142801 S2P_Lmt16_Under_RModule2_17 "电池模块放电电压二级恢复阈值";
CM_ SG_ 2418142802 S2P_Lmt16_Under_UModule1_18 "电池模块放电电压一级报警值";
CM_ SG_ 2418142802 S2P_Lmt16_Under_RModule1_18 "电池模块放电电压一级恢复阈值";
CM_ SG_ 2418142802 S2P_Lmt16_Under_UModule2_18 "电池模块放电电压二级报警值";
CM_ SG_ 2418142802 S2P_Lmt16_Under_RModule2_18 "电池模块放电电压二级恢复阈值";
CM_ SG_ 2418142803 S2P_Lmt16_Under_UModule1_19 "电池模块放电电压一级报警值";
CM_ SG_ 2418142803 S2P_Lmt16_Under_RModule1_19 "电池模块放电电压一级恢复阈值";
CM_ SG_ 2418142803 S2P_Lmt16_Under_UModule2_19 "电池模块放电电压二级报警值";
CM_ SG_ 2418142803 S2P_Lmt16_Under_RModule2_19 "电池模块放电电压二级恢复阈值";
CM_ SG_ 2418142804 S2P_Lmt16_Under_UModule1_20 "电池模块放电电压一级报警值";
CM_ SG_ 2418142804 S2P_Lmt16_Under_RModule1_20 "电池模块放电电压一级恢复阈值";
CM_ SG_ 2418142804 S2P_Lmt16_Under_UModule2_20 "电池模块放电电压二级报警值";
CM_ SG_ 2418142804 S2P_Lmt16_Under_RModule2_20 "电池模块放电电压二级恢复阈值";
CM_ SG_ 2418142805 S2P_Lmt16_Under_UModule1_21 "电池模块放电电压一级报警值";
CM_ SG_ 2418142805 S2P_Lmt16_Under_RModule1_21 "电池模块放电电压一级恢复阈值";
CM_ SG_ 2418142805 S2P_Lmt16_Under_UModule2_21 "电池模块放电电压二级报警值";
CM_ SG_ 2418142805 S2P_Lmt16_Under_RModule2_21 "电池模块放电电压二级恢复阈值";
CM_ SG_ 2418142806 S2P_Lmt16_Under_UModule1_22 "电池模块放电电压一级报警值";
CM_ SG_ 2418142806 S2P_Lmt16_Under_RModule1_22 "电池模块放电电压一级恢复阈值";
CM_ SG_ 2418142806 S2P_Lmt16_Under_UModule2_22 "电池模块放电电压二级报警值";
CM_ SG_ 2418142806 S2P_Lmt16_Under_RModule2_22 "电池模块放电电压二级恢复阈值";
CM_ SG_ 2418142807 S2P_Lmt16_Under_UModule1_23 "电池模块放电电压一级报警值";
CM_ SG_ 2418142807 S2P_Lmt16_Under_RModule1_23 "电池模块放电电压一级恢复阈值";
CM_ SG_ 2418142807 S2P_Lmt16_Under_UModule2_23 "电池模块放电电压二级报警值";
CM_ SG_ 2418142807 S2P_Lmt16_Under_RModule2_23 "电池模块放电电压二级恢复阈值";
CM_ SG_ 2418142808 S2P_Lmt16_Under_UModule1_24 "电池模块放电电压一级报警值";
CM_ SG_ 2418142808 S2P_Lmt16_Under_RModule1_24 "电池模块放电电压一级恢复阈值";
CM_ SG_ 2418142808 S2P_Lmt16_Under_UModule2_24 "电池模块放电电压二级报警值";
CM_ SG_ 2418142808 S2P_Lmt16_Under_RModule2_24 "电池模块放电电压二级恢复阈值";
CM_ SG_ 2418142809 S2P_Lmt16_Under_UModule1_25 "电池模块放电电压一级报警值";
CM_ SG_ 2418142809 S2P_Lmt16_Under_RModule1_25 "电池模块放电电压一级恢复阈值";
CM_ SG_ 2418142809 S2P_Lmt16_Under_UModule2_25 "电池模块放电电压二级报警值";
CM_ SG_ 2418142809 S2P_Lmt16_Under_RModule2_25 "电池模块放电电压二级恢复阈值";
CM_ SG_ 2418142810 S2P_Lmt16_Under_UModule1_26 "电池模块放电电压一级报警值";
CM_ SG_ 2418142810 S2P_Lmt16_Under_RModule1_26 "电池模块放电电压一级恢复阈值";
CM_ SG_ 2418142810 S2P_Lmt16_Under_UModule2_26 "电池模块放电电压二级报警值";
CM_ SG_ 2418142810 S2P_Lmt16_Under_RModule2_26 "电池模块放电电压二级恢复阈值";
CM_ SG_ 2418142811 S2P_Lmt16_Under_UModule1_27 "电池模块放电电压一级报警值";
CM_ SG_ 2418142811 S2P_Lmt16_Under_RModule1_27 "电池模块放电电压一级恢复阈值";
CM_ SG_ 2418142811 S2P_Lmt16_Under_UModule2_27 "电池模块放电电压二级报警值";
CM_ SG_ 2418142811 S2P_Lmt16_Under_RModule2_27 "电池模块放电电压二级恢复阈值";
CM_ SG_ 2418142812 S2P_Lmt16_Under_UModule1_28 "电池模块放电电压一级报警值";
CM_ SG_ 2418142812 S2P_Lmt16_Under_RModule1_28 "电池模块放电电压一级恢复阈值";
CM_ SG_ 2418142812 S2P_Lmt16_Under_UModule2_28 "电池模块放电电压二级报警值";
CM_ SG_ 2418142812 S2P_Lmt16_Under_RModule2_28 "电池模块放电电压二级恢复阈值";
CM_ SG_ 2418142813 S2P_Lmt16_Under_UModule1_29 "电池模块放电电压一级报警值";
CM_ SG_ 2418142813 S2P_Lmt16_Under_RModule1_29 "电池模块放电电压一级恢复阈值";
CM_ SG_ 2418142813 S2P_Lmt16_Under_UModule2_29 "电池模块放电电压二级报警值";
CM_ SG_ 2418142813 S2P_Lmt16_Under_RModule2_29 "电池模块放电电压二级恢复阈值";
CM_ SG_ 2418142814 S2P_Lmt16_Under_UModule1_30 "电池模块放电电压一级报警值";
CM_ SG_ 2418142814 S2P_Lmt16_Under_RModule1_30 "电池模块放电电压一级恢复阈值";
CM_ SG_ 2418142814 S2P_Lmt16_Under_UModule2_30 "电池模块放电电压二级报警值";
CM_ SG_ 2418142814 S2P_Lmt16_Under_RModule2_30 "电池模块放电电压二级恢复阈值";
CM_ SG_ 2418142815 S2P_Lmt16_Under_UModule1_31 "电池模块放电电压一级报警值";
CM_ SG_ 2418142815 S2P_Lmt16_Under_RModule1_31 "电池模块放电电压一级恢复阈值";
CM_ SG_ 2418142815 S2P_Lmt16_Under_UModule2_31 "电池模块放电电压二级报警值";
CM_ SG_ 2418142815 S2P_Lmt16_Under_RModule2_31 "电池模块放电电压二级恢复阈值";
CM_ SG_ 2418142816 S2P_Lmt16_Under_UModule1_32 "电池模块放电电压一级报警值";
CM_ SG_ 2418142816 S2P_Lmt16_Under_RModule1_32 "电池模块放电电压一级恢复阈值";
CM_ SG_ 2418142816 S2P_Lmt16_Under_UModule2_32 "电池模块放电电压二级报警值";
CM_ SG_ 2418142816 S2P_Lmt16_Under_RModule2_32 "电池模块放电电压二级恢复阈值";
CM_ SG_ 2418142817 S2P_Lmt16_Under_UModule1_33 "电池模块放电电压一级报警值";
CM_ SG_ 2418142817 S2P_Lmt16_Under_RModule1_33 "电池模块放电电压一级恢复阈值";
CM_ SG_ 2418142817 S2P_Lmt16_Under_UModule2_33 "电池模块放电电压二级报警值";
CM_ SG_ 2418142817 S2P_Lmt16_Under_RModule2_33 "电池模块放电电压二级恢复阈值";
CM_ SG_ 2418142818 S2P_Lmt16_Under_UModule1_34 "电池模块放电电压一级报警值";
CM_ SG_ 2418142818 S2P_Lmt16_Under_RModule1_34 "电池模块放电电压一级恢复阈值";
CM_ SG_ 2418142818 S2P_Lmt16_Under_UModule2_34 "电池模块放电电压二级报警值";
CM_ SG_ 2418142818 S2P_Lmt16_Under_RModule2_34 "电池模块放电电压二级恢复阈值";
CM_ SG_ 2418142819 S2P_Lmt16_Under_UModule1_35 "电池模块放电电压一级报警值";
CM_ SG_ 2418142819 S2P_Lmt16_Under_RModule1_35 "电池模块放电电压一级恢复阈值";
CM_ SG_ 2418142819 S2P_Lmt16_Under_UModule2_35 "电池模块放电电压二级报警值";
CM_ SG_ 2418142819 S2P_Lmt16_Under_RModule2_35 "电池模块放电电压二级恢复阈值";
CM_ SG_ 2418142820 S2P_Lmt16_Under_UModule1_36 "电池模块放电电压一级报警值";
CM_ SG_ 2418142820 S2P_Lmt16_Under_RModule1_36 "电池模块放电电压一级恢复阈值";
CM_ SG_ 2418142820 S2P_Lmt16_Under_UModule2_36 "电池模块放电电压二级报警值";
CM_ SG_ 2418142820 S2P_Lmt16_Under_RModule2_36 "电池模块放电电压二级恢复阈值";
CM_ SG_ 2418142821 S2P_Lmt16_Under_UModule1_37 "电池模块放电电压一级报警值";
CM_ SG_ 2418142821 S2P_Lmt16_Under_RModule1_37 "电池模块放电电压一级恢复阈值";
CM_ SG_ 2418142821 S2P_Lmt16_Under_UModule2_37 "电池模块放电电压二级报警值";
CM_ SG_ 2418142821 S2P_Lmt16_Under_RModule2_37 "电池模块放电电压二级恢复阈值";
CM_ SG_ 2418142822 S2P_Lmt16_Under_UModule1_38 "电池模块放电电压一级报警值";
CM_ SG_ 2418142822 S2P_Lmt16_Under_RModule1_38 "电池模块放电电压一级恢复阈值";
CM_ SG_ 2418142822 S2P_Lmt16_Under_UModule2_38 "电池模块放电电压二级报警值";
CM_ SG_ 2418142822 S2P_Lmt16_Under_RModule2_38 "电池模块放电电压二级恢复阈值";
CM_ SG_ 2418142823 S2P_Lmt16_Under_UModule1_39 "电池模块放电电压一级报警值";
CM_ SG_ 2418142823 S2P_Lmt16_Under_RModule1_39 "电池模块放电电压一级恢复阈值";
CM_ SG_ 2418142823 S2P_Lmt16_Under_UModule2_39 "电池模块放电电压二级报警值";
CM_ SG_ 2418142823 S2P_Lmt16_Under_RModule2_39 "电池模块放电电压二级恢复阈值";
CM_ SG_ 2418142824 S2P_Lmt16_Under_UModule1_40 "电池模块放电电压一级报警值";
CM_ SG_ 2418142824 S2P_Lmt16_Under_RModule1_40 "电池模块放电电压一级恢复阈值";
CM_ SG_ 2418142824 S2P_Lmt16_Under_UModule2_40 "电池模块放电电压二级报警值";
CM_ SG_ 2418142824 S2P_Lmt16_Under_RModule2_40 "电池模块放电电压二级恢复阈值";
CM_ SG_ 2418142825 S2P_Lmt16_Under_UModule1_41 "电池模块放电电压一级报警值";
CM_ SG_ 2418142825 S2P_Lmt16_Under_RModule1_41 "电池模块放电电压一级恢复阈值";
CM_ SG_ 2418142825 S2P_Lmt16_Under_UModule2_41 "电池模块放电电压二级报警值";
CM_ SG_ 2418142825 S2P_Lmt16_Under_RModule2_41 "电池模块放电电压二级恢复阈值";
CM_ SG_ 2418142826 S2P_Lmt16_Under_UModule1_42 "电池模块放电电压一级报警值";
CM_ SG_ 2418142826 S2P_Lmt16_Under_RModule1_42 "电池模块放电电压一级恢复阈值";
CM_ SG_ 2418142826 S2P_Lmt16_Under_UModule2_42 "电池模块放电电压二级报警值";
CM_ SG_ 2418142826 S2P_Lmt16_Under_RModule2_42 "电池模块放电电压二级恢复阈值";
CM_ SG_ 2418142827 S2P_Lmt16_Under_UModule1_43 "电池模块放电电压一级报警值";
CM_ SG_ 2418142827 S2P_Lmt16_Under_RModule1_43 "电池模块放电电压一级恢复阈值";
CM_ SG_ 2418142827 S2P_Lmt16_Under_UModule2_43 "电池模块放电电压二级报警值";
CM_ SG_ 2418142827 S2P_Lmt16_Under_RModule2_43 "电池模块放电电压二级恢复阈值";
CM_ SG_ 2418142828 S2P_Lmt16_Under_UModule1_44 "电池模块放电电压一级报警值";
CM_ SG_ 2418142828 S2P_Lmt16_Under_RModule1_44 "电池模块放电电压一级恢复阈值";
CM_ SG_ 2418142828 S2P_Lmt16_Under_UModule2_44 "电池模块放电电压二级报警值";
CM_ SG_ 2418142828 S2P_Lmt16_Under_RModule2_44 "电池模块放电电压二级恢复阈值";
CM_ SG_ 2418142829 S2P_Lmt16_Under_UModule1_45 "电池模块放电电压一级报警值";
CM_ SG_ 2418142829 S2P_Lmt16_Under_RModule1_45 "电池模块放电电压一级恢复阈值";
CM_ SG_ 2418142829 S2P_Lmt16_Under_UModule2_45 "电池模块放电电压二级报警值";
CM_ SG_ 2418142829 S2P_Lmt16_Under_RModule2_45 "电池模块放电电压二级恢复阈值";
CM_ SG_ 2418142830 S2P_Lmt16_Under_UModule1_46 "电池模块放电电压一级报警值";
CM_ SG_ 2418142830 S2P_Lmt16_Under_RModule1_46 "电池模块放电电压一级恢复阈值";
CM_ SG_ 2418142830 S2P_Lmt16_Under_UModule2_46 "电池模块放电电压二级报警值";
CM_ SG_ 2418142830 S2P_Lmt16_Under_RModule2_46 "电池模块放电电压二级恢复阈值";
CM_ SG_ 2418142831 S2P_Lmt16_Under_UModule1_47 "电池模块放电电压一级报警值";
CM_ SG_ 2418142831 S2P_Lmt16_Under_RModule1_47 "电池模块放电电压一级恢复阈值";
CM_ SG_ 2418142831 S2P_Lmt16_Under_UModule2_47 "电池模块放电电压二级报警值";
CM_ SG_ 2418142831 S2P_Lmt16_Under_RModule2_47 "电池模块放电电压二级恢复阈值";
CM_ SG_ 2418142832 S2P_Lmt16_Under_UModule1_48 "电池模块放电电压一级报警值";
CM_ SG_ 2418142832 S2P_Lmt16_Under_RModule1_48 "电池模块放电电压一级恢复阈值";
CM_ SG_ 2418142832 S2P_Lmt16_Under_UModule2_48 "电池模块放电电压二级报警值";
CM_ SG_ 2418142832 S2P_Lmt16_Under_RModule2_48 "电池模块放电电压二级恢复阈值";
CM_ SG_ 2418142833 S2P_Lmt16_Under_UModule1_49 "电池模块放电电压一级报警值";
CM_ SG_ 2418142833 S2P_Lmt16_Under_RModule1_49 "电池模块放电电压一级恢复阈值";
CM_ SG_ 2418142833 S2P_Lmt16_Under_UModule2_49 "电池模块放电电压二级报警值";
CM_ SG_ 2418142833 S2P_Lmt16_Under_RModule2_49 "电池模块放电电压二级恢复阈值";
CM_ SG_ 2418142834 S2P_Lmt16_Under_UModule1_50 "电池模块放电电压一级报警值";
CM_ SG_ 2418142834 S2P_Lmt16_Under_RModule1_50 "电池模块放电电压一级恢复阈值";
CM_ SG_ 2418142834 S2P_Lmt16_Under_UModule2_50 "电池模块放电电压二级报警值";
CM_ SG_ 2418142834 S2P_Lmt16_Under_RModule2_50 "电池模块放电电压二级恢复阈值";
CM_ SG_ 2418142835 S2P_Lmt16_Under_UModule1_51 "电池模块放电电压一级报警值";
CM_ SG_ 2418142835 S2P_Lmt16_Under_RModule1_51 "电池模块放电电压一级恢复阈值";
CM_ SG_ 2418142835 S2P_Lmt16_Under_UModule2_51 "电池模块放电电压二级报警值";
CM_ SG_ 2418142835 S2P_Lmt16_Under_RModule2_51 "电池模块放电电压二级恢复阈值";
CM_ SG_ 2418142836 S2P_Lmt16_Under_UModule1_52 "电池模块放电电压一级报警值";
CM_ SG_ 2418142836 S2P_Lmt16_Under_RModule1_52 "电池模块放电电压一级恢复阈值";
CM_ SG_ 2418142836 S2P_Lmt16_Under_UModule2_52 "电池模块放电电压二级报警值";
CM_ SG_ 2418142836 S2P_Lmt16_Under_RModule2_52 "电池模块放电电压二级恢复阈值";
CM_ SG_ 2418142837 S2P_Lmt16_Under_UModule1_53 "电池模块放电电压一级报警值";
CM_ SG_ 2418142837 S2P_Lmt16_Under_RModule1_53 "电池模块放电电压一级恢复阈值";
CM_ SG_ 2418142837 S2P_Lmt16_Under_UModule2_53 "电池模块放电电压二级报警值";
CM_ SG_ 2418142837 S2P_Lmt16_Under_RModule2_53 "电池模块放电电压二级恢复阈值";
CM_ SG_ 2418142838 S2P_Lmt16_Under_UModule1_54 "电池模块放电电压一级报警值";
CM_ SG_ 2418142838 S2P_Lmt16_Under_RModule1_54 "电池模块放电电压一级恢复阈值";
CM_ SG_ 2418142838 S2P_Lmt16_Under_UModule2_54 "电池模块放电电压二级报警值";
CM_ SG_ 2418142838 S2P_Lmt16_Under_RModule2_54 "电池模块放电电压二级恢复阈值";
CM_ SG_ 2418142839 S2P_Lmt16_Under_UModule1_55 "电池模块放电电压一级报警值";
CM_ SG_ 2418142839 S2P_Lmt16_Under_RModule1_55 "电池模块放电电压一级恢复阈值";
CM_ SG_ 2418142839 S2P_Lmt16_Under_UModule2_55 "电池模块放电电压二级报警值";
CM_ SG_ 2418142839 S2P_Lmt16_Under_RModule2_55 "电池模块放电电压二级恢复阈值";
CM_ SG_ 2418142840 S2P_Lmt16_Under_UModule1_56 "电池模块放电电压一级报警值";
CM_ SG_ 2418142840 S2P_Lmt16_Under_RModule1_56 "电池模块放电电压一级恢复阈值";
CM_ SG_ 2418142840 S2P_Lmt16_Under_UModule2_56 "电池模块放电电压二级报警值";
CM_ SG_ 2418142840 S2P_Lmt16_Under_RModule2_56 "电池模块放电电压二级恢复阈值";
CM_ SG_ 2418142841 S2P_Lmt16_Under_UModule1_57 "电池模块放电电压一级报警值";
CM_ SG_ 2418142841 S2P_Lmt16_Under_RModule1_57 "电池模块放电电压一级恢复阈值";
CM_ SG_ 2418142841 S2P_Lmt16_Under_UModule2_57 "电池模块放电电压二级报警值";
CM_ SG_ 2418142841 S2P_Lmt16_Under_RModule2_57 "电池模块放电电压二级恢复阈值";
CM_ SG_ 2418142842 S2P_Lmt16_Under_UModule1_58 "电池模块放电电压一级报警值";
CM_ SG_ 2418142842 S2P_Lmt16_Under_RModule1_58 "电池模块放电电压一级恢复阈值";
CM_ SG_ 2418142842 S2P_Lmt16_Under_UModule2_58 "电池模块放电电压二级报警值";
CM_ SG_ 2418142842 S2P_Lmt16_Under_RModule2_58 "电池模块放电电压二级恢复阈值";
CM_ SG_ 2418142843 S2P_Lmt16_Under_UModule1_59 "电池模块放电电压一级报警值";
CM_ SG_ 2418142843 S2P_Lmt16_Under_RModule1_59 "电池模块放电电压一级恢复阈值";
CM_ SG_ 2418142843 S2P_Lmt16_Under_UModule2_59 "电池模块放电电压二级报警值";
CM_ SG_ 2418142843 S2P_Lmt16_Under_RModule2_59 "电池模块放电电压二级恢复阈值";
CM_ SG_ 2418142844 S2P_Lmt16_Under_UModule1_60 "电池模块放电电压一级报警值";
CM_ SG_ 2418142844 S2P_Lmt16_Under_RModule1_60 "电池模块放电电压一级恢复阈值";
CM_ SG_ 2418142844 S2P_Lmt16_Under_UModule2_60 "电池模块放电电压二级报警值";
CM_ SG_ 2418142844 S2P_Lmt16_Under_RModule2_60 "电池模块放电电压二级恢复阈值";
CM_ SG_ 2418142845 S2P_Lmt16_Under_UModule1_61 "电池模块放电电压一级报警值";
CM_ SG_ 2418142845 S2P_Lmt16_Under_RModule1_61 "电池模块放电电压一级恢复阈值";
CM_ SG_ 2418142845 S2P_Lmt16_Under_UModule2_61 "电池模块放电电压二级报警值";
CM_ SG_ 2418142845 S2P_Lmt16_Under_RModule2_61 "电池模块放电电压二级恢复阈值";
CM_ SG_ 2418142846 S2P_Lmt16_Under_UModule1_62 "电池模块放电电压一级报警值";
CM_ SG_ 2418142846 S2P_Lmt16_Under_RModule1_62 "电池模块放电电压一级恢复阈值";
CM_ SG_ 2418142846 S2P_Lmt16_Under_UModule2_62 "电池模块放电电压二级报警值";
CM_ SG_ 2418142846 S2P_Lmt16_Under_RModule2_62 "电池模块放电电压二级恢复阈值";
CM_ SG_ 2418142847 S2P_Lmt16_Under_UModule1_63 "电池模块放电电压一级报警值";
CM_ SG_ 2418142847 S2P_Lmt16_Under_RModule1_63 "电池模块放电电压一级恢复阈值";
CM_ SG_ 2418142847 S2P_Lmt16_Under_UModule2_63 "电池模块放电电压二级报警值";
CM_ SG_ 2418142847 S2P_Lmt16_Under_RModule2_63 "电池模块放电电压二级恢复阈值";
CM_ SG_ 2418208321 S2P_Lmt17_Over_UModule3_01 "电池模块充电电压三级报警值";
CM_ SG_ 2418208321 S2P_Lmt17_Under_UModule3_01 "电池模块放电电压三级报警值";
CM_ SG_ 2418208321 S2P_Lmt17_Over_UModule4_01 "电池模块充电截止电压";
CM_ SG_ 2418208321 S2P_Lmt17_Under_UModule4_01 "电池模块放电截止电压";
CM_ SG_ 2418208322 S2P_Lmt17_Over_UModule3_02 "电池模块充电电压三级报警值";
CM_ SG_ 2418208322 S2P_Lmt17_Under_UModule3_02 "电池模块放电电压三级报警值";
CM_ SG_ 2418208322 S2P_Lmt17_Over_UModule4_02 "电池模块充电截止电压";
CM_ SG_ 2418208322 S2P_Lmt17_Under_UModule4_02 "电池模块放电截止电压";
CM_ SG_ 2418208323 S2P_Lmt17_Over_UModule3_03 "电池模块充电电压三级报警值";
CM_ SG_ 2418208323 S2P_Lmt17_Under_UModule3_03 "电池模块放电电压三级报警值";
CM_ SG_ 2418208323 S2P_Lmt17_Over_UModule4_03 "电池模块充电截止电压";
CM_ SG_ 2418208323 S2P_Lmt17_Under_UModule4_03 "电池模块放电截止电压";
CM_ SG_ 2418208324 S2P_Lmt17_Over_UModule3_04 "电池模块充电电压三级报警值";
CM_ SG_ 2418208324 S2P_Lmt17_Under_UModule3_04 "电池模块放电电压三级报警值";
CM_ SG_ 2418208324 S2P_Lmt17_Over_UModule4_04 "电池模块充电截止电压";
CM_ SG_ 2418208324 S2P_Lmt17_Under_UModule4_04 "电池模块放电截止电压";
CM_ SG_ 2418208325 S2P_Lmt17_Over_UModule3_05 "电池模块充电电压三级报警值";
CM_ SG_ 2418208325 S2P_Lmt17_Under_UModule3_05 "电池模块放电电压三级报警值";
CM_ SG_ 2418208325 S2P_Lmt17_Over_UModule4_05 "电池模块充电截止电压";
CM_ SG_ 2418208325 S2P_Lmt17_Under_UModule4_05 "电池模块放电截止电压";
CM_ SG_ 2418208326 S2P_Lmt17_Over_UModule3_06 "电池模块充电电压三级报警值";
CM_ SG_ 2418208326 S2P_Lmt17_Under_UModule3_06 "电池模块放电电压三级报警值";
CM_ SG_ 2418208326 S2P_Lmt17_Over_UModule4_06 "电池模块充电截止电压";
CM_ SG_ 2418208326 S2P_Lmt17_Under_UModule4_06 "电池模块放电截止电压";
CM_ SG_ 2418208327 S2P_Lmt17_Over_UModule3_07 "电池模块充电电压三级报警值";
CM_ SG_ 2418208327 S2P_Lmt17_Under_UModule3_07 "电池模块放电电压三级报警值";
CM_ SG_ 2418208327 S2P_Lmt17_Over_UModule4_07 "电池模块充电截止电压";
CM_ SG_ 2418208327 S2P_Lmt17_Under_UModule4_07 "电池模块放电截止电压";
CM_ SG_ 2418208328 S2P_Lmt17_Over_UModule3_08 "电池模块充电电压三级报警值";
CM_ SG_ 2418208328 S2P_Lmt17_Under_UModule3_08 "电池模块放电电压三级报警值";
CM_ SG_ 2418208328 S2P_Lmt17_Over_UModule4_08 "电池模块充电截止电压";
CM_ SG_ 2418208328 S2P_Lmt17_Under_UModule4_08 "电池模块放电截止电压";
CM_ SG_ 2418208329 S2P_Lmt17_Over_UModule3_09 "电池模块充电电压三级报警值";
CM_ SG_ 2418208329 S2P_Lmt17_Under_UModule3_09 "电池模块放电电压三级报警值";
CM_ SG_ 2418208329 S2P_Lmt17_Over_UModule4_09 "电池模块充电截止电压";
CM_ SG_ 2418208329 S2P_Lmt17_Under_UModule4_09 "电池模块放电截止电压";
CM_ SG_ 2418208330 S2P_Lmt17_Over_UModule3_10 "电池模块充电电压三级报警值";
CM_ SG_ 2418208330 S2P_Lmt17_Under_UModule3_10 "电池模块放电电压三级报警值";
CM_ SG_ 2418208330 S2P_Lmt17_Over_UModule4_10 "电池模块充电截止电压";
CM_ SG_ 2418208330 S2P_Lmt17_Under_UModule4_10 "电池模块放电截止电压";
CM_ SG_ 2418208331 S2P_Lmt17_Over_UModule3_11 "电池模块充电电压三级报警值";
CM_ SG_ 2418208331 S2P_Lmt17_Under_UModule3_11 "电池模块放电电压三级报警值";
CM_ SG_ 2418208331 S2P_Lmt17_Over_UModule4_11 "电池模块充电截止电压";
CM_ SG_ 2418208331 S2P_Lmt17_Under_UModule4_11 "电池模块放电截止电压";
CM_ SG_ 2418208332 S2P_Lmt17_Over_UModule3_12 "电池模块充电电压三级报警值";
CM_ SG_ 2418208332 S2P_Lmt17_Under_UModule3_12 "电池模块放电电压三级报警值";
CM_ SG_ 2418208332 S2P_Lmt17_Over_UModule4_12 "电池模块充电截止电压";
CM_ SG_ 2418208332 S2P_Lmt17_Under_UModule4_12 "电池模块放电截止电压";
CM_ SG_ 2418208333 S2P_Lmt17_Over_UModule3_13 "电池模块充电电压三级报警值";
CM_ SG_ 2418208333 S2P_Lmt17_Under_UModule3_13 "电池模块放电电压三级报警值";
CM_ SG_ 2418208333 S2P_Lmt17_Over_UModule4_13 "电池模块充电截止电压";
CM_ SG_ 2418208333 S2P_Lmt17_Under_UModule4_13 "电池模块放电截止电压";
CM_ SG_ 2418208334 S2P_Lmt17_Over_UModule3_14 "电池模块充电电压三级报警值";
CM_ SG_ 2418208334 S2P_Lmt17_Under_UModule3_14 "电池模块放电电压三级报警值";
CM_ SG_ 2418208334 S2P_Lmt17_Over_UModule4_14 "电池模块充电截止电压";
CM_ SG_ 2418208334 S2P_Lmt17_Under_UModule4_14 "电池模块放电截止电压";
CM_ SG_ 2418208335 S2P_Lmt17_Over_UModule3_15 "电池模块充电电压三级报警值";
CM_ SG_ 2418208335 S2P_Lmt17_Under_UModule3_15 "电池模块放电电压三级报警值";
CM_ SG_ 2418208335 S2P_Lmt17_Over_UModule4_15 "电池模块充电截止电压";
CM_ SG_ 2418208335 S2P_Lmt17_Under_UModule4_15 "电池模块放电截止电压";
CM_ SG_ 2418208336 S2P_Lmt17_Over_UModule3_16 "电池模块充电电压三级报警值";
CM_ SG_ 2418208336 S2P_Lmt17_Under_UModule3_16 "电池模块放电电压三级报警值";
CM_ SG_ 2418208336 S2P_Lmt17_Over_UModule4_16 "电池模块充电截止电压";
CM_ SG_ 2418208336 S2P_Lmt17_Under_UModule4_16 "电池模块放电截止电压";
CM_ SG_ 2418208337 S2P_Lmt17_Over_UModule3_17 "电池模块充电电压三级报警值";
CM_ SG_ 2418208337 S2P_Lmt17_Under_UModule3_17 "电池模块放电电压三级报警值";
CM_ SG_ 2418208337 S2P_Lmt17_Over_UModule4_17 "电池模块充电截止电压";
CM_ SG_ 2418208337 S2P_Lmt17_Under_UModule4_17 "电池模块放电截止电压";
CM_ SG_ 2418208338 S2P_Lmt17_Over_UModule3_18 "电池模块充电电压三级报警值";
CM_ SG_ 2418208338 S2P_Lmt17_Under_UModule3_18 "电池模块放电电压三级报警值";
CM_ SG_ 2418208338 S2P_Lmt17_Over_UModule4_18 "电池模块充电截止电压";
CM_ SG_ 2418208338 S2P_Lmt17_Under_UModule4_18 "电池模块放电截止电压";
CM_ SG_ 2418208339 S2P_Lmt17_Over_UModule3_19 "电池模块充电电压三级报警值";
CM_ SG_ 2418208339 S2P_Lmt17_Under_UModule3_19 "电池模块放电电压三级报警值";
CM_ SG_ 2418208339 S2P_Lmt17_Over_UModule4_19 "电池模块充电截止电压";
CM_ SG_ 2418208339 S2P_Lmt17_Under_UModule4_19 "电池模块放电截止电压";
CM_ SG_ 2418208340 S2P_Lmt17_Over_UModule3_20 "电池模块充电电压三级报警值";
CM_ SG_ 2418208340 S2P_Lmt17_Under_UModule3_20 "电池模块放电电压三级报警值";
CM_ SG_ 2418208340 S2P_Lmt17_Over_UModule4_20 "电池模块充电截止电压";
CM_ SG_ 2418208340 S2P_Lmt17_Under_UModule4_20 "电池模块放电截止电压";
CM_ SG_ 2418208341 S2P_Lmt17_Over_UModule3_21 "电池模块充电电压三级报警值";
CM_ SG_ 2418208341 S2P_Lmt17_Under_UModule3_21 "电池模块放电电压三级报警值";
CM_ SG_ 2418208341 S2P_Lmt17_Over_UModule4_21 "电池模块充电截止电压";
CM_ SG_ 2418208341 S2P_Lmt17_Under_UModule4_21 "电池模块放电截止电压";
CM_ SG_ 2418208342 S2P_Lmt17_Over_UModule3_22 "电池模块充电电压三级报警值";
CM_ SG_ 2418208342 S2P_Lmt17_Under_UModule3_22 "电池模块放电电压三级报警值";
CM_ SG_ 2418208342 S2P_Lmt17_Over_UModule4_22 "电池模块充电截止电压";
CM_ SG_ 2418208342 S2P_Lmt17_Under_UModule4_22 "电池模块放电截止电压";
CM_ SG_ 2418208343 S2P_Lmt17_Over_UModule3_23 "电池模块充电电压三级报警值";
CM_ SG_ 2418208343 S2P_Lmt17_Under_UModule3_23 "电池模块放电电压三级报警值";
CM_ SG_ 2418208343 S2P_Lmt17_Over_UModule4_23 "电池模块充电截止电压";
CM_ SG_ 2418208343 S2P_Lmt17_Under_UModule4_23 "电池模块放电截止电压";
CM_ SG_ 2418208344 S2P_Lmt17_Over_UModule3_24 "电池模块充电电压三级报警值";
CM_ SG_ 2418208344 S2P_Lmt17_Under_UModule3_24 "电池模块放电电压三级报警值";
CM_ SG_ 2418208344 S2P_Lmt17_Over_UModule4_24 "电池模块充电截止电压";
CM_ SG_ 2418208344 S2P_Lmt17_Under_UModule4_24 "电池模块放电截止电压";
CM_ SG_ 2418208345 S2P_Lmt17_Over_UModule3_25 "电池模块充电电压三级报警值";
CM_ SG_ 2418208345 S2P_Lmt17_Under_UModule3_25 "电池模块放电电压三级报警值";
CM_ SG_ 2418208345 S2P_Lmt17_Over_UModule4_25 "电池模块充电截止电压";
CM_ SG_ 2418208345 S2P_Lmt17_Under_UModule4_25 "电池模块放电截止电压";
CM_ SG_ 2418208346 S2P_Lmt17_Over_UModule3_26 "电池模块充电电压三级报警值";
CM_ SG_ 2418208346 S2P_Lmt17_Under_UModule3_26 "电池模块放电电压三级报警值";
CM_ SG_ 2418208346 S2P_Lmt17_Over_UModule4_26 "电池模块充电截止电压";
CM_ SG_ 2418208346 S2P_Lmt17_Under_UModule4_26 "电池模块放电截止电压";
CM_ SG_ 2418208347 S2P_Lmt17_Over_UModule3_27 "电池模块充电电压三级报警值";
CM_ SG_ 2418208347 S2P_Lmt17_Under_UModule3_27 "电池模块放电电压三级报警值";
CM_ SG_ 2418208347 S2P_Lmt17_Over_UModule4_27 "电池模块充电截止电压";
CM_ SG_ 2418208347 S2P_Lmt17_Under_UModule4_27 "电池模块放电截止电压";
CM_ SG_ 2418208348 S2P_Lmt17_Over_UModule3_28 "电池模块充电电压三级报警值";
CM_ SG_ 2418208348 S2P_Lmt17_Under_UModule3_28 "电池模块放电电压三级报警值";
CM_ SG_ 2418208348 S2P_Lmt17_Over_UModule4_28 "电池模块充电截止电压";
CM_ SG_ 2418208348 S2P_Lmt17_Under_UModule4_28 "电池模块放电截止电压";
CM_ SG_ 2418208349 S2P_Lmt17_Over_UModule3_29 "电池模块充电电压三级报警值";
CM_ SG_ 2418208349 S2P_Lmt17_Under_UModule3_29 "电池模块放电电压三级报警值";
CM_ SG_ 2418208349 S2P_Lmt17_Over_UModule4_29 "电池模块充电截止电压";
CM_ SG_ 2418208349 S2P_Lmt17_Under_UModule4_29 "电池模块放电截止电压";
CM_ SG_ 2418208350 S2P_Lmt17_Over_UModule3_30 "电池模块充电电压三级报警值";
CM_ SG_ 2418208350 S2P_Lmt17_Under_UModule3_30 "电池模块放电电压三级报警值";
CM_ SG_ 2418208350 S2P_Lmt17_Over_UModule4_30 "电池模块充电截止电压";
CM_ SG_ 2418208350 S2P_Lmt17_Under_UModule4_30 "电池模块放电截止电压";
CM_ SG_ 2418208351 S2P_Lmt17_Over_UModule3_31 "电池模块充电电压三级报警值";
CM_ SG_ 2418208351 S2P_Lmt17_Under_UModule3_31 "电池模块放电电压三级报警值";
CM_ SG_ 2418208351 S2P_Lmt17_Over_UModule4_31 "电池模块充电截止电压";
CM_ SG_ 2418208351 S2P_Lmt17_Under_UModule4_31 "电池模块放电截止电压";
CM_ SG_ 2418208352 S2P_Lmt17_Over_UModule3_32 "电池模块充电电压三级报警值";
CM_ SG_ 2418208352 S2P_Lmt17_Under_UModule3_32 "电池模块放电电压三级报警值";
CM_ SG_ 2418208352 S2P_Lmt17_Over_UModule4_32 "电池模块充电截止电压";
CM_ SG_ 2418208352 S2P_Lmt17_Under_UModule4_32 "电池模块放电截止电压";
CM_ SG_ 2418208353 S2P_Lmt17_Over_UModule3_33 "电池模块充电电压三级报警值";
CM_ SG_ 2418208353 S2P_Lmt17_Under_UModule3_33 "电池模块放电电压三级报警值";
CM_ SG_ 2418208353 S2P_Lmt17_Over_UModule4_33 "电池模块充电截止电压";
CM_ SG_ 2418208353 S2P_Lmt17_Under_UModule4_33 "电池模块放电截止电压";
CM_ SG_ 2418208354 S2P_Lmt17_Over_UModule3_34 "电池模块充电电压三级报警值";
CM_ SG_ 2418208354 S2P_Lmt17_Under_UModule3_34 "电池模块放电电压三级报警值";
CM_ SG_ 2418208354 S2P_Lmt17_Over_UModule4_34 "电池模块充电截止电压";
CM_ SG_ 2418208354 S2P_Lmt17_Under_UModule4_34 "电池模块放电截止电压";
CM_ SG_ 2418208355 S2P_Lmt17_Over_UModule3_35 "电池模块充电电压三级报警值";
CM_ SG_ 2418208355 S2P_Lmt17_Under_UModule3_35 "电池模块放电电压三级报警值";
CM_ SG_ 2418208355 S2P_Lmt17_Over_UModule4_35 "电池模块充电截止电压";
CM_ SG_ 2418208355 S2P_Lmt17_Under_UModule4_35 "电池模块放电截止电压";
CM_ SG_ 2418208356 S2P_Lmt17_Over_UModule3_36 "电池模块充电电压三级报警值";
CM_ SG_ 2418208356 S2P_Lmt17_Under_UModule3_36 "电池模块放电电压三级报警值";
CM_ SG_ 2418208356 S2P_Lmt17_Over_UModule4_36 "电池模块充电截止电压";
CM_ SG_ 2418208356 S2P_Lmt17_Under_UModule4_36 "电池模块放电截止电压";
CM_ SG_ 2418208357 S2P_Lmt17_Over_UModule3_37 "电池模块充电电压三级报警值";
CM_ SG_ 2418208357 S2P_Lmt17_Under_UModule3_37 "电池模块放电电压三级报警值";
CM_ SG_ 2418208357 S2P_Lmt17_Over_UModule4_37 "电池模块充电截止电压";
CM_ SG_ 2418208357 S2P_Lmt17_Under_UModule4_37 "电池模块放电截止电压";
CM_ SG_ 2418208358 S2P_Lmt17_Over_UModule3_38 "电池模块充电电压三级报警值";
CM_ SG_ 2418208358 S2P_Lmt17_Under_UModule3_38 "电池模块放电电压三级报警值";
CM_ SG_ 2418208358 S2P_Lmt17_Over_UModule4_38 "电池模块充电截止电压";
CM_ SG_ 2418208358 S2P_Lmt17_Under_UModule4_38 "电池模块放电截止电压";
CM_ SG_ 2418208359 S2P_Lmt17_Over_UModule3_39 "电池模块充电电压三级报警值";
CM_ SG_ 2418208359 S2P_Lmt17_Under_UModule3_39 "电池模块放电电压三级报警值";
CM_ SG_ 2418208359 S2P_Lmt17_Over_UModule4_39 "电池模块充电截止电压";
CM_ SG_ 2418208359 S2P_Lmt17_Under_UModule4_39 "电池模块放电截止电压";
CM_ SG_ 2418208360 S2P_Lmt17_Over_UModule3_40 "电池模块充电电压三级报警值";
CM_ SG_ 2418208360 S2P_Lmt17_Under_UModule3_40 "电池模块放电电压三级报警值";
CM_ SG_ 2418208360 S2P_Lmt17_Over_UModule4_40 "电池模块充电截止电压";
CM_ SG_ 2418208360 S2P_Lmt17_Under_UModule4_40 "电池模块放电截止电压";
CM_ SG_ 2418208361 S2P_Lmt17_Over_UModule3_41 "电池模块充电电压三级报警值";
CM_ SG_ 2418208361 S2P_Lmt17_Under_UModule3_41 "电池模块放电电压三级报警值";
CM_ SG_ 2418208361 S2P_Lmt17_Over_UModule4_41 "电池模块充电截止电压";
CM_ SG_ 2418208361 S2P_Lmt17_Under_UModule4_41 "电池模块放电截止电压";
CM_ SG_ 2418208362 S2P_Lmt17_Over_UModule3_42 "电池模块充电电压三级报警值";
CM_ SG_ 2418208362 S2P_Lmt17_Under_UModule3_42 "电池模块放电电压三级报警值";
CM_ SG_ 2418208362 S2P_Lmt17_Over_UModule4_42 "电池模块充电截止电压";
CM_ SG_ 2418208362 S2P_Lmt17_Under_UModule4_42 "电池模块放电截止电压";
CM_ SG_ 2418208363 S2P_Lmt17_Over_UModule3_43 "电池模块充电电压三级报警值";
CM_ SG_ 2418208363 S2P_Lmt17_Under_UModule3_43 "电池模块放电电压三级报警值";
CM_ SG_ 2418208363 S2P_Lmt17_Over_UModule4_43 "电池模块充电截止电压";
CM_ SG_ 2418208363 S2P_Lmt17_Under_UModule4_43 "电池模块放电截止电压";
CM_ SG_ 2418208364 S2P_Lmt17_Over_UModule3_44 "电池模块充电电压三级报警值";
CM_ SG_ 2418208364 S2P_Lmt17_Under_UModule3_44 "电池模块放电电压三级报警值";
CM_ SG_ 2418208364 S2P_Lmt17_Over_UModule4_44 "电池模块充电截止电压";
CM_ SG_ 2418208364 S2P_Lmt17_Under_UModule4_44 "电池模块放电截止电压";
CM_ SG_ 2418208365 S2P_Lmt17_Over_UModule3_45 "电池模块充电电压三级报警值";
CM_ SG_ 2418208365 S2P_Lmt17_Under_UModule3_45 "电池模块放电电压三级报警值";
CM_ SG_ 2418208365 S2P_Lmt17_Over_UModule4_45 "电池模块充电截止电压";
CM_ SG_ 2418208365 S2P_Lmt17_Under_UModule4_45 "电池模块放电截止电压";
CM_ SG_ 2418208366 S2P_Lmt17_Over_UModule3_46 "电池模块充电电压三级报警值";
CM_ SG_ 2418208366 S2P_Lmt17_Under_UModule3_46 "电池模块放电电压三级报警值";
CM_ SG_ 2418208366 S2P_Lmt17_Over_UModule4_46 "电池模块充电截止电压";
CM_ SG_ 2418208366 S2P_Lmt17_Under_UModule4_46 "电池模块放电截止电压";
CM_ SG_ 2418208367 S2P_Lmt17_Over_UModule3_47 "电池模块充电电压三级报警值";
CM_ SG_ 2418208367 S2P_Lmt17_Under_UModule3_47 "电池模块放电电压三级报警值";
CM_ SG_ 2418208367 S2P_Lmt17_Over_UModule4_47 "电池模块充电截止电压";
CM_ SG_ 2418208367 S2P_Lmt17_Under_UModule4_47 "电池模块放电截止电压";
CM_ SG_ 2418208368 S2P_Lmt17_Over_UModule3_48 "电池模块充电电压三级报警值";
CM_ SG_ 2418208368 S2P_Lmt17_Under_UModule3_48 "电池模块放电电压三级报警值";
CM_ SG_ 2418208368 S2P_Lmt17_Over_UModule4_48 "电池模块充电截止电压";
CM_ SG_ 2418208368 S2P_Lmt17_Under_UModule4_48 "电池模块放电截止电压";
CM_ SG_ 2418208369 S2P_Lmt17_Over_UModule3_49 "电池模块充电电压三级报警值";
CM_ SG_ 2418208369 S2P_Lmt17_Under_UModule3_49 "电池模块放电电压三级报警值";
CM_ SG_ 2418208369 S2P_Lmt17_Over_UModule4_49 "电池模块充电截止电压";
CM_ SG_ 2418208369 S2P_Lmt17_Under_UModule4_49 "电池模块放电截止电压";
CM_ SG_ 2418208370 S2P_Lmt17_Over_UModule3_50 "电池模块充电电压三级报警值";
CM_ SG_ 2418208370 S2P_Lmt17_Under_UModule3_50 "电池模块放电电压三级报警值";
CM_ SG_ 2418208370 S2P_Lmt17_Over_UModule4_50 "电池模块充电截止电压";
CM_ SG_ 2418208370 S2P_Lmt17_Under_UModule4_50 "电池模块放电截止电压";
CM_ SG_ 2418208371 S2P_Lmt17_Over_UModule3_51 "电池模块充电电压三级报警值";
CM_ SG_ 2418208371 S2P_Lmt17_Under_UModule3_51 "电池模块放电电压三级报警值";
CM_ SG_ 2418208371 S2P_Lmt17_Over_UModule4_51 "电池模块充电截止电压";
CM_ SG_ 2418208371 S2P_Lmt17_Under_UModule4_51 "电池模块放电截止电压";
CM_ SG_ 2418208372 S2P_Lmt17_Over_UModule3_52 "电池模块充电电压三级报警值";
CM_ SG_ 2418208372 S2P_Lmt17_Under_UModule3_52 "电池模块放电电压三级报警值";
CM_ SG_ 2418208372 S2P_Lmt17_Over_UModule4_52 "电池模块充电截止电压";
CM_ SG_ 2418208372 S2P_Lmt17_Under_UModule4_52 "电池模块放电截止电压";
CM_ SG_ 2418208373 S2P_Lmt17_Over_UModule3_53 "电池模块充电电压三级报警值";
CM_ SG_ 2418208373 S2P_Lmt17_Under_UModule3_53 "电池模块放电电压三级报警值";
CM_ SG_ 2418208373 S2P_Lmt17_Over_UModule4_53 "电池模块充电截止电压";
CM_ SG_ 2418208373 S2P_Lmt17_Under_UModule4_53 "电池模块放电截止电压";
CM_ SG_ 2418208374 S2P_Lmt17_Over_UModule3_54 "电池模块充电电压三级报警值";
CM_ SG_ 2418208374 S2P_Lmt17_Under_UModule3_54 "电池模块放电电压三级报警值";
CM_ SG_ 2418208374 S2P_Lmt17_Over_UModule4_54 "电池模块充电截止电压";
CM_ SG_ 2418208374 S2P_Lmt17_Under_UModule4_54 "电池模块放电截止电压";
CM_ SG_ 2418208375 S2P_Lmt17_Over_UModule3_55 "电池模块充电电压三级报警值";
CM_ SG_ 2418208375 S2P_Lmt17_Under_UModule3_55 "电池模块放电电压三级报警值";
CM_ SG_ 2418208375 S2P_Lmt17_Over_UModule4_55 "电池模块充电截止电压";
CM_ SG_ 2418208375 S2P_Lmt17_Under_UModule4_55 "电池模块放电截止电压";
CM_ SG_ 2418208376 S2P_Lmt17_Over_UModule3_56 "电池模块充电电压三级报警值";
CM_ SG_ 2418208376 S2P_Lmt17_Under_UModule3_56 "电池模块放电电压三级报警值";
CM_ SG_ 2418208376 S2P_Lmt17_Over_UModule4_56 "电池模块充电截止电压";
CM_ SG_ 2418208376 S2P_Lmt17_Under_UModule4_56 "电池模块放电截止电压";
CM_ SG_ 2418208377 S2P_Lmt17_Over_UModule3_57 "电池模块充电电压三级报警值";
CM_ SG_ 2418208377 S2P_Lmt17_Under_UModule3_57 "电池模块放电电压三级报警值";
CM_ SG_ 2418208377 S2P_Lmt17_Over_UModule4_57 "电池模块充电截止电压";
CM_ SG_ 2418208377 S2P_Lmt17_Under_UModule4_57 "电池模块放电截止电压";
CM_ SG_ 2418208378 S2P_Lmt17_Over_UModule3_58 "电池模块充电电压三级报警值";
CM_ SG_ 2418208378 S2P_Lmt17_Under_UModule3_58 "电池模块放电电压三级报警值";
CM_ SG_ 2418208378 S2P_Lmt17_Over_UModule4_58 "电池模块充电截止电压";
CM_ SG_ 2418208378 S2P_Lmt17_Under_UModule4_58 "电池模块放电截止电压";
CM_ SG_ 2418208379 S2P_Lmt17_Over_UModule3_59 "电池模块充电电压三级报警值";
CM_ SG_ 2418208379 S2P_Lmt17_Under_UModule3_59 "电池模块放电电压三级报警值";
CM_ SG_ 2418208379 S2P_Lmt17_Over_UModule4_59 "电池模块充电截止电压";
CM_ SG_ 2418208379 S2P_Lmt17_Under_UModule4_59 "电池模块放电截止电压";
CM_ SG_ 2418208380 S2P_Lmt17_Over_UModule3_60 "电池模块充电电压三级报警值";
CM_ SG_ 2418208380 S2P_Lmt17_Under_UModule3_60 "电池模块放电电压三级报警值";
CM_ SG_ 2418208380 S2P_Lmt17_Over_UModule4_60 "电池模块充电截止电压";
CM_ SG_ 2418208380 S2P_Lmt17_Under_UModule4_60 "电池模块放电截止电压";
CM_ SG_ 2418208381 S2P_Lmt17_Over_UModule3_61 "电池模块充电电压三级报警值";
CM_ SG_ 2418208381 S2P_Lmt17_Under_UModule3_61 "电池模块放电电压三级报警值";
CM_ SG_ 2418208381 S2P_Lmt17_Over_UModule4_61 "电池模块充电截止电压";
CM_ SG_ 2418208381 S2P_Lmt17_Under_UModule4_61 "电池模块放电截止电压";
CM_ SG_ 2418208382 S2P_Lmt17_Over_UModule3_62 "电池模块充电电压三级报警值";
CM_ SG_ 2418208382 S2P_Lmt17_Under_UModule3_62 "电池模块放电电压三级报警值";
CM_ SG_ 2418208382 S2P_Lmt17_Over_UModule4_62 "电池模块充电截止电压";
CM_ SG_ 2418208382 S2P_Lmt17_Under_UModule4_62 "电池模块放电截止电压";
CM_ SG_ 2418208383 S2P_Lmt17_Over_UModule3_63 "电池模块充电电压三级报警值";
CM_ SG_ 2418208383 S2P_Lmt17_Under_UModule3_63 "电池模块放电电压三级报警值";
CM_ SG_ 2418208383 S2P_Lmt17_Over_UModule4_63 "电池模块充电截止电压";
CM_ SG_ 2418208383 S2P_Lmt17_Under_UModule4_63 "电池模块放电截止电压";
CM_ SG_ 2400710209 S2P_Detail_UCSC1_01 "1号CSC总压";
CM_ SG_ 2400710209 S2P_Detail_UCSC2_01 "2号CSC总压";
CM_ SG_ 2400710209 S2P_Detail_UCSC3_01 "3号CSC总压";
CM_ SG_ 2400710209 S2P_Detail_UCSC4_01 "4号CSC总压";
CM_ SG_ 2400710209 S2P_Detail_UCSC5_01 "5号CSC总压";
CM_ SG_ 2400710209 S2P_Detail_Reserved_01 "预留";
CM_ SG_ 2400710210 S2P_Detail_UCSC1_02 "1号CSC总压";
CM_ SG_ 2400710210 S2P_Detail_UCSC2_02 "2号CSC总压";
CM_ SG_ 2400710210 S2P_Detail_UCSC3_02 "3号CSC总压";
CM_ SG_ 2400710210 S2P_Detail_UCSC4_02 "4号CSC总压";
CM_ SG_ 2400710210 S2P_Detail_UCSC5_02 "5号CSC总压";
CM_ SG_ 2400710210 S2P_Detail_Reserved_02 "预留";
CM_ SG_ 2400710211 S2P_Detail_UCSC1_03 "1号CSC总压";
CM_ SG_ 2400710211 S2P_Detail_UCSC2_03 "2号CSC总压";
CM_ SG_ 2400710211 S2P_Detail_UCSC3_03 "3号CSC总压";
CM_ SG_ 2400710211 S2P_Detail_UCSC4_03 "4号CSC总压";
CM_ SG_ 2400710211 S2P_Detail_UCSC5_03 "5号CSC总压";
CM_ SG_ 2400710211 S2P_Detail_Reserved_03 "预留";
CM_ SG_ 2400710212 S2P_Detail_UCSC1_04 "1号CSC总压";
CM_ SG_ 2400710212 S2P_Detail_UCSC2_04 "2号CSC总压";
CM_ SG_ 2400710212 S2P_Detail_UCSC3_04 "3号CSC总压";
CM_ SG_ 2400710212 S2P_Detail_UCSC4_04 "4号CSC总压";
CM_ SG_ 2400710212 S2P_Detail_UCSC5_04 "5号CSC总压";
CM_ SG_ 2400710212 S2P_Detail_Reserved_04 "预留";
CM_ SG_ 2400710213 S2P_Detail_UCSC1_05 "1号CSC总压";
CM_ SG_ 2400710213 S2P_Detail_UCSC2_05 "2号CSC总压";
CM_ SG_ 2400710213 S2P_Detail_UCSC3_05 "3号CSC总压";
CM_ SG_ 2400710213 S2P_Detail_UCSC4_05 "4号CSC总压";
CM_ SG_ 2400710213 S2P_Detail_UCSC5_05 "5号CSC总压";
CM_ SG_ 2400710213 S2P_Detail_Reserved_05 "预留";
CM_ SG_ 2400710214 S2P_Detail_UCSC1_06 "1号CSC总压";
CM_ SG_ 2400710214 S2P_Detail_UCSC2_06 "2号CSC总压";
CM_ SG_ 2400710214 S2P_Detail_UCSC3_06 "3号CSC总压";
CM_ SG_ 2400710214 S2P_Detail_UCSC4_06 "4号CSC总压";
CM_ SG_ 2400710214 S2P_Detail_UCSC5_06 "5号CSC总压";
CM_ SG_ 2400710214 S2P_Detail_Reserved_06 "预留";
CM_ SG_ 2400710215 S2P_Detail_UCSC1_07 "1号CSC总压";
CM_ SG_ 2400710215 S2P_Detail_UCSC2_07 "2号CSC总压";
CM_ SG_ 2400710215 S2P_Detail_UCSC3_07 "3号CSC总压";
CM_ SG_ 2400710215 S2P_Detail_UCSC4_07 "4号CSC总压";
CM_ SG_ 2400710215 S2P_Detail_UCSC5_07 "5号CSC总压";
CM_ SG_ 2400710215 S2P_Detail_Reserved_07 "预留";
CM_ SG_ 2400710216 S2P_Detail_UCSC1_08 "1号CSC总压";
CM_ SG_ 2400710216 S2P_Detail_UCSC2_08 "2号CSC总压";
CM_ SG_ 2400710216 S2P_Detail_UCSC3_08 "3号CSC总压";
CM_ SG_ 2400710216 S2P_Detail_UCSC4_08 "4号CSC总压";
CM_ SG_ 2400710216 S2P_Detail_UCSC5_08 "5号CSC总压";
CM_ SG_ 2400710216 S2P_Detail_Reserved_08 "预留";
CM_ SG_ 2400710217 S2P_Detail_UCSC1_09 "1号CSC总压";
CM_ SG_ 2400710217 S2P_Detail_UCSC2_09 "2号CSC总压";
CM_ SG_ 2400710217 S2P_Detail_UCSC3_09 "3号CSC总压";
CM_ SG_ 2400710217 S2P_Detail_UCSC4_09 "4号CSC总压";
CM_ SG_ 2400710217 S2P_Detail_UCSC5_09 "5号CSC总压";
CM_ SG_ 2400710217 S2P_Detail_Reserved_09 "预留";
CM_ SG_ 2400710218 S2P_Detail_UCSC1_10 "1号CSC总压";
CM_ SG_ 2400710218 S2P_Detail_UCSC2_10 "2号CSC总压";
CM_ SG_ 2400710218 S2P_Detail_UCSC3_10 "3号CSC总压";
CM_ SG_ 2400710218 S2P_Detail_UCSC4_10 "4号CSC总压";
CM_ SG_ 2400710218 S2P_Detail_UCSC5_10 "5号CSC总压";
CM_ SG_ 2400710218 S2P_Detail_Reserved_10 "预留";
CM_ SG_ 2400710219 S2P_Detail_UCSC1_11 "1号CSC总压";
CM_ SG_ 2400710219 S2P_Detail_UCSC2_11 "2号CSC总压";
CM_ SG_ 2400710219 S2P_Detail_UCSC3_11 "3号CSC总压";
CM_ SG_ 2400710219 S2P_Detail_UCSC4_11 "4号CSC总压";
CM_ SG_ 2400710219 S2P_Detail_UCSC5_11 "5号CSC总压";
CM_ SG_ 2400710219 S2P_Detail_Reserved_11 "预留";
CM_ SG_ 2400710220 S2P_Detail_UCSC1_12 "1号CSC总压";
CM_ SG_ 2400710220 S2P_Detail_UCSC2_12 "2号CSC总压";
CM_ SG_ 2400710220 S2P_Detail_UCSC3_12 "3号CSC总压";
CM_ SG_ 2400710220 S2P_Detail_UCSC4_12 "4号CSC总压";
CM_ SG_ 2400710220 S2P_Detail_UCSC5_12 "5号CSC总压";
CM_ SG_ 2400710220 S2P_Detail_Reserved_12 "预留";
CM_ SG_ 2400710221 S2P_Detail_UCSC1_13 "1号CSC总压";
CM_ SG_ 2400710221 S2P_Detail_UCSC2_13 "2号CSC总压";
CM_ SG_ 2400710221 S2P_Detail_UCSC3_13 "3号CSC总压";
CM_ SG_ 2400710221 S2P_Detail_UCSC4_13 "4号CSC总压";
CM_ SG_ 2400710221 S2P_Detail_UCSC5_13 "5号CSC总压";
CM_ SG_ 2400710221 S2P_Detail_Reserved_13 "预留";
CM_ SG_ 2400710222 S2P_Detail_UCSC1_14 "1号CSC总压";
CM_ SG_ 2400710222 S2P_Detail_UCSC2_14 "2号CSC总压";
CM_ SG_ 2400710222 S2P_Detail_UCSC3_14 "3号CSC总压";
CM_ SG_ 2400710222 S2P_Detail_UCSC4_14 "4号CSC总压";
CM_ SG_ 2400710222 S2P_Detail_UCSC5_14 "5号CSC总压";
CM_ SG_ 2400710222 S2P_Detail_Reserved_14 "预留";
CM_ SG_ 2400710223 S2P_Detail_UCSC1_15 "1号CSC总压";
CM_ SG_ 2400710223 S2P_Detail_UCSC2_15 "2号CSC总压";
CM_ SG_ 2400710223 S2P_Detail_UCSC3_15 "3号CSC总压";
CM_ SG_ 2400710223 S2P_Detail_UCSC4_15 "4号CSC总压";
CM_ SG_ 2400710223 S2P_Detail_UCSC5_15 "5号CSC总压";
CM_ SG_ 2400710223 S2P_Detail_Reserved_15 "预留";
CM_ SG_ 2400710224 S2P_Detail_UCSC1_16 "1号CSC总压";
CM_ SG_ 2400710224 S2P_Detail_UCSC2_16 "2号CSC总压";
CM_ SG_ 2400710224 S2P_Detail_UCSC3_16 "3号CSC总压";
CM_ SG_ 2400710224 S2P_Detail_UCSC4_16 "4号CSC总压";
CM_ SG_ 2400710224 S2P_Detail_UCSC5_16 "5号CSC总压";
CM_ SG_ 2400710224 S2P_Detail_Reserved_16 "预留";
CM_ SG_ 2400710225 S2P_Detail_UCSC1_17 "1号CSC总压";
CM_ SG_ 2400710225 S2P_Detail_UCSC2_17 "2号CSC总压";
CM_ SG_ 2400710225 S2P_Detail_UCSC3_17 "3号CSC总压";
CM_ SG_ 2400710225 S2P_Detail_UCSC4_17 "4号CSC总压";
CM_ SG_ 2400710225 S2P_Detail_UCSC5_17 "5号CSC总压";
CM_ SG_ 2400710225 S2P_Detail_Reserved_17 "预留";
CM_ SG_ 2400710226 S2P_Detail_UCSC1_18 "1号CSC总压";
CM_ SG_ 2400710226 S2P_Detail_UCSC2_18 "2号CSC总压";
CM_ SG_ 2400710226 S2P_Detail_UCSC3_18 "3号CSC总压";
CM_ SG_ 2400710226 S2P_Detail_UCSC4_18 "4号CSC总压";
CM_ SG_ 2400710226 S2P_Detail_UCSC5_18 "5号CSC总压";
CM_ SG_ 2400710226 S2P_Detail_Reserved_18 "预留";
CM_ SG_ 2400710227 S2P_Detail_UCSC1_19 "1号CSC总压";
CM_ SG_ 2400710227 S2P_Detail_UCSC2_19 "2号CSC总压";
CM_ SG_ 2400710227 S2P_Detail_UCSC3_19 "3号CSC总压";
CM_ SG_ 2400710227 S2P_Detail_UCSC4_19 "4号CSC总压";
CM_ SG_ 2400710227 S2P_Detail_UCSC5_19 "5号CSC总压";
CM_ SG_ 2400710227 S2P_Detail_Reserved_19 "预留";
CM_ SG_ 2400710228 S2P_Detail_UCSC1_20 "1号CSC总压";
CM_ SG_ 2400710228 S2P_Detail_UCSC2_20 "2号CSC总压";
CM_ SG_ 2400710228 S2P_Detail_UCSC3_20 "3号CSC总压";
CM_ SG_ 2400710228 S2P_Detail_UCSC4_20 "4号CSC总压";
CM_ SG_ 2400710228 S2P_Detail_UCSC5_20 "5号CSC总压";
CM_ SG_ 2400710228 S2P_Detail_Reserved_20 "预留";
CM_ SG_ 2400710229 S2P_Detail_UCSC1_21 "1号CSC总压";
CM_ SG_ 2400710229 S2P_Detail_UCSC2_21 "2号CSC总压";
CM_ SG_ 2400710229 S2P_Detail_UCSC3_21 "3号CSC总压";
CM_ SG_ 2400710229 S2P_Detail_UCSC4_21 "4号CSC总压";
CM_ SG_ 2400710229 S2P_Detail_UCSC5_21 "5号CSC总压";
CM_ SG_ 2400710229 S2P_Detail_Reserved_21 "预留";
CM_ SG_ 2400710230 S2P_Detail_UCSC1_22 "1号CSC总压";
CM_ SG_ 2400710230 S2P_Detail_UCSC2_22 "2号CSC总压";
CM_ SG_ 2400710230 S2P_Detail_UCSC3_22 "3号CSC总压";
CM_ SG_ 2400710230 S2P_Detail_UCSC4_22 "4号CSC总压";
CM_ SG_ 2400710230 S2P_Detail_UCSC5_22 "5号CSC总压";
CM_ SG_ 2400710230 S2P_Detail_Reserved_22 "预留";
CM_ SG_ 2400710231 S2P_Detail_UCSC1_23 "1号CSC总压";
CM_ SG_ 2400710231 S2P_Detail_UCSC2_23 "2号CSC总压";
CM_ SG_ 2400710231 S2P_Detail_UCSC3_23 "3号CSC总压";
CM_ SG_ 2400710231 S2P_Detail_UCSC4_23 "4号CSC总压";
CM_ SG_ 2400710231 S2P_Detail_UCSC5_23 "5号CSC总压";
CM_ SG_ 2400710231 S2P_Detail_Reserved_23 "预留";
CM_ SG_ 2400710232 S2P_Detail_UCSC1_24 "1号CSC总压";
CM_ SG_ 2400710232 S2P_Detail_UCSC2_24 "2号CSC总压";
CM_ SG_ 2400710232 S2P_Detail_UCSC3_24 "3号CSC总压";
CM_ SG_ 2400710232 S2P_Detail_UCSC4_24 "4号CSC总压";
CM_ SG_ 2400710232 S2P_Detail_UCSC5_24 "5号CSC总压";
CM_ SG_ 2400710232 S2P_Detail_Reserved_24 "预留";
CM_ SG_ 2400710233 S2P_Detail_UCSC1_25 "1号CSC总压";
CM_ SG_ 2400710233 S2P_Detail_UCSC2_25 "2号CSC总压";
CM_ SG_ 2400710233 S2P_Detail_UCSC3_25 "3号CSC总压";
CM_ SG_ 2400710233 S2P_Detail_UCSC4_25 "4号CSC总压";
CM_ SG_ 2400710233 S2P_Detail_UCSC5_25 "5号CSC总压";
CM_ SG_ 2400710233 S2P_Detail_Reserved_25 "预留";
CM_ SG_ 2400710234 S2P_Detail_UCSC1_26 "1号CSC总压";
CM_ SG_ 2400710234 S2P_Detail_UCSC2_26 "2号CSC总压";
CM_ SG_ 2400710234 S2P_Detail_UCSC3_26 "3号CSC总压";
CM_ SG_ 2400710234 S2P_Detail_UCSC4_26 "4号CSC总压";
CM_ SG_ 2400710234 S2P_Detail_UCSC5_26 "5号CSC总压";
CM_ SG_ 2400710234 S2P_Detail_Reserved_26 "预留";
CM_ SG_ 2400710235 S2P_Detail_UCSC1_27 "1号CSC总压";
CM_ SG_ 2400710235 S2P_Detail_UCSC2_27 "2号CSC总压";
CM_ SG_ 2400710235 S2P_Detail_UCSC3_27 "3号CSC总压";
CM_ SG_ 2400710235 S2P_Detail_UCSC4_27 "4号CSC总压";
CM_ SG_ 2400710235 S2P_Detail_UCSC5_27 "5号CSC总压";
CM_ SG_ 2400710235 S2P_Detail_Reserved_27 "预留";
CM_ SG_ 2400710236 S2P_Detail_UCSC1_28 "1号CSC总压";
CM_ SG_ 2400710236 S2P_Detail_UCSC2_28 "2号CSC总压";
CM_ SG_ 2400710236 S2P_Detail_UCSC3_28 "3号CSC总压";
CM_ SG_ 2400710236 S2P_Detail_UCSC4_28 "4号CSC总压";
CM_ SG_ 2400710236 S2P_Detail_UCSC5_28 "5号CSC总压";
CM_ SG_ 2400710236 S2P_Detail_Reserved_28 "预留";
CM_ SG_ 2400710237 S2P_Detail_UCSC1_29 "1号CSC总压";
CM_ SG_ 2400710237 S2P_Detail_UCSC2_29 "2号CSC总压";
CM_ SG_ 2400710237 S2P_Detail_UCSC3_29 "3号CSC总压";
CM_ SG_ 2400710237 S2P_Detail_UCSC4_29 "4号CSC总压";
CM_ SG_ 2400710237 S2P_Detail_UCSC5_29 "5号CSC总压";
CM_ SG_ 2400710237 S2P_Detail_Reserved_29 "预留";
CM_ SG_ 2400710238 S2P_Detail_UCSC1_30 "1号CSC总压";
CM_ SG_ 2400710238 S2P_Detail_UCSC2_30 "2号CSC总压";
CM_ SG_ 2400710238 S2P_Detail_UCSC3_30 "3号CSC总压";
CM_ SG_ 2400710238 S2P_Detail_UCSC4_30 "4号CSC总压";
CM_ SG_ 2400710238 S2P_Detail_UCSC5_30 "5号CSC总压";
CM_ SG_ 2400710238 S2P_Detail_Reserved_30 "预留";
CM_ SG_ 2400710239 S2P_Detail_UCSC1_31 "1号CSC总压";
CM_ SG_ 2400710239 S2P_Detail_UCSC2_31 "2号CSC总压";
CM_ SG_ 2400710239 S2P_Detail_UCSC3_31 "3号CSC总压";
CM_ SG_ 2400710239 S2P_Detail_UCSC4_31 "4号CSC总压";
CM_ SG_ 2400710239 S2P_Detail_UCSC5_31 "5号CSC总压";
CM_ SG_ 2400710239 S2P_Detail_Reserved_31 "预留";
CM_ SG_ 2400710240 S2P_Detail_UCSC1_32 "1号CSC总压";
CM_ SG_ 2400710240 S2P_Detail_UCSC2_32 "2号CSC总压";
CM_ SG_ 2400710240 S2P_Detail_UCSC3_32 "3号CSC总压";
CM_ SG_ 2400710240 S2P_Detail_UCSC4_32 "4号CSC总压";
CM_ SG_ 2400710240 S2P_Detail_UCSC5_32 "5号CSC总压";
CM_ SG_ 2400710240 S2P_Detail_Reserved_32 "预留";
CM_ SG_ 2400710241 S2P_Detail_UCSC1_33 "1号CSC总压";
CM_ SG_ 2400710241 S2P_Detail_UCSC2_33 "2号CSC总压";
CM_ SG_ 2400710241 S2P_Detail_UCSC3_33 "3号CSC总压";
CM_ SG_ 2400710241 S2P_Detail_UCSC4_33 "4号CSC总压";
CM_ SG_ 2400710241 S2P_Detail_UCSC5_33 "5号CSC总压";
CM_ SG_ 2400710241 S2P_Detail_Reserved_33 "预留";
CM_ SG_ 2400710242 S2P_Detail_UCSC1_34 "1号CSC总压";
CM_ SG_ 2400710242 S2P_Detail_UCSC2_34 "2号CSC总压";
CM_ SG_ 2400710242 S2P_Detail_UCSC3_34 "3号CSC总压";
CM_ SG_ 2400710242 S2P_Detail_UCSC4_34 "4号CSC总压";
CM_ SG_ 2400710242 S2P_Detail_UCSC5_34 "5号CSC总压";
CM_ SG_ 2400710242 S2P_Detail_Reserved_34 "预留";
CM_ SG_ 2400710243 S2P_Detail_UCSC1_35 "1号CSC总压";
CM_ SG_ 2400710243 S2P_Detail_UCSC2_35 "2号CSC总压";
CM_ SG_ 2400710243 S2P_Detail_UCSC3_35 "3号CSC总压";
CM_ SG_ 2400710243 S2P_Detail_UCSC4_35 "4号CSC总压";
CM_ SG_ 2400710243 S2P_Detail_UCSC5_35 "5号CSC总压";
CM_ SG_ 2400710243 S2P_Detail_Reserved_35 "预留";
CM_ SG_ 2400710244 S2P_Detail_UCSC1_36 "1号CSC总压";
CM_ SG_ 2400710244 S2P_Detail_UCSC2_36 "2号CSC总压";
CM_ SG_ 2400710244 S2P_Detail_UCSC3_36 "3号CSC总压";
CM_ SG_ 2400710244 S2P_Detail_UCSC4_36 "4号CSC总压";
CM_ SG_ 2400710244 S2P_Detail_UCSC5_36 "5号CSC总压";
CM_ SG_ 2400710244 S2P_Detail_Reserved_36 "预留";
CM_ SG_ 2400710245 S2P_Detail_UCSC1_37 "1号CSC总压";
CM_ SG_ 2400710245 S2P_Detail_UCSC2_37 "2号CSC总压";
CM_ SG_ 2400710245 S2P_Detail_UCSC3_37 "3号CSC总压";
CM_ SG_ 2400710245 S2P_Detail_UCSC4_37 "4号CSC总压";
CM_ SG_ 2400710245 S2P_Detail_UCSC5_37 "5号CSC总压";
CM_ SG_ 2400710245 S2P_Detail_Reserved_37 "预留";
CM_ SG_ 2400710246 S2P_Detail_UCSC1_38 "1号CSC总压";
CM_ SG_ 2400710246 S2P_Detail_UCSC2_38 "2号CSC总压";
CM_ SG_ 2400710246 S2P_Detail_UCSC3_38 "3号CSC总压";
CM_ SG_ 2400710246 S2P_Detail_UCSC4_38 "4号CSC总压";
CM_ SG_ 2400710246 S2P_Detail_UCSC5_38 "5号CSC总压";
CM_ SG_ 2400710246 S2P_Detail_Reserved_38 "预留";
CM_ SG_ 2400710247 S2P_Detail_UCSC1_39 "1号CSC总压";
CM_ SG_ 2400710247 S2P_Detail_UCSC2_39 "2号CSC总压";
CM_ SG_ 2400710247 S2P_Detail_UCSC3_39 "3号CSC总压";
CM_ SG_ 2400710247 S2P_Detail_UCSC4_39 "4号CSC总压";
CM_ SG_ 2400710247 S2P_Detail_UCSC5_39 "5号CSC总压";
CM_ SG_ 2400710247 S2P_Detail_Reserved_39 "预留";
CM_ SG_ 2400710248 S2P_Detail_UCSC1_40 "1号CSC总压";
CM_ SG_ 2400710248 S2P_Detail_UCSC2_40 "2号CSC总压";
CM_ SG_ 2400710248 S2P_Detail_UCSC3_40 "3号CSC总压";
CM_ SG_ 2400710248 S2P_Detail_UCSC4_40 "4号CSC总压";
CM_ SG_ 2400710248 S2P_Detail_UCSC5_40 "5号CSC总压";
CM_ SG_ 2400710248 S2P_Detail_Reserved_40 "预留";
CM_ SG_ 2400710249 S2P_Detail_UCSC1_41 "1号CSC总压";
CM_ SG_ 2400710249 S2P_Detail_UCSC2_41 "2号CSC总压";
CM_ SG_ 2400710249 S2P_Detail_UCSC3_41 "3号CSC总压";
CM_ SG_ 2400710249 S2P_Detail_UCSC4_41 "4号CSC总压";
CM_ SG_ 2400710249 S2P_Detail_UCSC5_41 "5号CSC总压";
CM_ SG_ 2400710249 S2P_Detail_Reserved_41 "预留";
CM_ SG_ 2400710250 S2P_Detail_UCSC1_42 "1号CSC总压";
CM_ SG_ 2400710250 S2P_Detail_UCSC2_42 "2号CSC总压";
CM_ SG_ 2400710250 S2P_Detail_UCSC3_42 "3号CSC总压";
CM_ SG_ 2400710250 S2P_Detail_UCSC4_42 "4号CSC总压";
CM_ SG_ 2400710250 S2P_Detail_UCSC5_42 "5号CSC总压";
CM_ SG_ 2400710250 S2P_Detail_Reserved_42 "预留";
CM_ SG_ 2400710251 S2P_Detail_UCSC1_43 "1号CSC总压";
CM_ SG_ 2400710251 S2P_Detail_UCSC2_43 "2号CSC总压";
CM_ SG_ 2400710251 S2P_Detail_UCSC3_43 "3号CSC总压";
CM_ SG_ 2400710251 S2P_Detail_UCSC4_43 "4号CSC总压";
CM_ SG_ 2400710251 S2P_Detail_UCSC5_43 "5号CSC总压";
CM_ SG_ 2400710251 S2P_Detail_Reserved_43 "预留";
CM_ SG_ 2400710252 S2P_Detail_UCSC1_44 "1号CSC总压";
CM_ SG_ 2400710252 S2P_Detail_UCSC2_44 "2号CSC总压";
CM_ SG_ 2400710252 S2P_Detail_UCSC3_44 "3号CSC总压";
CM_ SG_ 2400710252 S2P_Detail_UCSC4_44 "4号CSC总压";
CM_ SG_ 2400710252 S2P_Detail_UCSC5_44 "5号CSC总压";
CM_ SG_ 2400710252 S2P_Detail_Reserved_44 "预留";
CM_ SG_ 2400710253 S2P_Detail_UCSC1_45 "1号CSC总压";
CM_ SG_ 2400710253 S2P_Detail_UCSC2_45 "2号CSC总压";
CM_ SG_ 2400710253 S2P_Detail_UCSC3_45 "3号CSC总压";
CM_ SG_ 2400710253 S2P_Detail_UCSC4_45 "4号CSC总压";
CM_ SG_ 2400710253 S2P_Detail_UCSC5_45 "5号CSC总压";
CM_ SG_ 2400710253 S2P_Detail_Reserved_45 "预留";
CM_ SG_ 2400710254 S2P_Detail_UCSC1_46 "1号CSC总压";
CM_ SG_ 2400710254 S2P_Detail_UCSC2_46 "2号CSC总压";
CM_ SG_ 2400710254 S2P_Detail_UCSC3_46 "3号CSC总压";
CM_ SG_ 2400710254 S2P_Detail_UCSC4_46 "4号CSC总压";
CM_ SG_ 2400710254 S2P_Detail_UCSC5_46 "5号CSC总压";
CM_ SG_ 2400710254 S2P_Detail_Reserved_46 "预留";
CM_ SG_ 2400710255 S2P_Detail_UCSC1_47 "1号CSC总压";
CM_ SG_ 2400710255 S2P_Detail_UCSC2_47 "2号CSC总压";
CM_ SG_ 2400710255 S2P_Detail_UCSC3_47 "3号CSC总压";
CM_ SG_ 2400710255 S2P_Detail_UCSC4_47 "4号CSC总压";
CM_ SG_ 2400710255 S2P_Detail_UCSC5_47 "5号CSC总压";
CM_ SG_ 2400710255 S2P_Detail_Reserved_47 "预留";
CM_ SG_ 2400710256 S2P_Detail_UCSC1_48 "1号CSC总压";
CM_ SG_ 2400710256 S2P_Detail_UCSC2_48 "2号CSC总压";
CM_ SG_ 2400710256 S2P_Detail_UCSC3_48 "3号CSC总压";
CM_ SG_ 2400710256 S2P_Detail_UCSC4_48 "4号CSC总压";
CM_ SG_ 2400710256 S2P_Detail_UCSC5_48 "5号CSC总压";
CM_ SG_ 2400710256 S2P_Detail_Reserved_48 "预留";
CM_ SG_ 2400710257 S2P_Detail_UCSC1_49 "1号CSC总压";
CM_ SG_ 2400710257 S2P_Detail_UCSC2_49 "2号CSC总压";
CM_ SG_ 2400710257 S2P_Detail_UCSC3_49 "3号CSC总压";
CM_ SG_ 2400710257 S2P_Detail_UCSC4_49 "4号CSC总压";
CM_ SG_ 2400710257 S2P_Detail_UCSC5_49 "5号CSC总压";
CM_ SG_ 2400710257 S2P_Detail_Reserved_49 "预留";
CM_ SG_ 2400710258 S2P_Detail_UCSC1_50 "1号CSC总压";
CM_ SG_ 2400710258 S2P_Detail_UCSC2_50 "2号CSC总压";
CM_ SG_ 2400710258 S2P_Detail_UCSC3_50 "3号CSC总压";
CM_ SG_ 2400710258 S2P_Detail_UCSC4_50 "4号CSC总压";
CM_ SG_ 2400710258 S2P_Detail_UCSC5_50 "5号CSC总压";
CM_ SG_ 2400710258 S2P_Detail_Reserved_50 "预留";
CM_ SG_ 2400710259 S2P_Detail_UCSC1_51 "1号CSC总压";
CM_ SG_ 2400710259 S2P_Detail_UCSC2_51 "2号CSC总压";
CM_ SG_ 2400710259 S2P_Detail_UCSC3_51 "3号CSC总压";
CM_ SG_ 2400710259 S2P_Detail_UCSC4_51 "4号CSC总压";
CM_ SG_ 2400710259 S2P_Detail_UCSC5_51 "5号CSC总压";
CM_ SG_ 2400710259 S2P_Detail_Reserved_51 "预留";
CM_ SG_ 2400710260 S2P_Detail_UCSC1_52 "1号CSC总压";
CM_ SG_ 2400710260 S2P_Detail_UCSC2_52 "2号CSC总压";
CM_ SG_ 2400710260 S2P_Detail_UCSC3_52 "3号CSC总压";
CM_ SG_ 2400710260 S2P_Detail_UCSC4_52 "4号CSC总压";
CM_ SG_ 2400710260 S2P_Detail_UCSC5_52 "5号CSC总压";
CM_ SG_ 2400710260 S2P_Detail_Reserved_52 "预留";
CM_ SG_ 2400710261 S2P_Detail_UCSC1_53 "1号CSC总压";
CM_ SG_ 2400710261 S2P_Detail_UCSC2_53 "2号CSC总压";
CM_ SG_ 2400710261 S2P_Detail_UCSC3_53 "3号CSC总压";
CM_ SG_ 2400710261 S2P_Detail_UCSC4_53 "4号CSC总压";
CM_ SG_ 2400710261 S2P_Detail_UCSC5_53 "5号CSC总压";
CM_ SG_ 2400710261 S2P_Detail_Reserved_53 "预留";
CM_ SG_ 2400710262 S2P_Detail_UCSC1_54 "1号CSC总压";
CM_ SG_ 2400710262 S2P_Detail_UCSC2_54 "2号CSC总压";
CM_ SG_ 2400710262 S2P_Detail_UCSC3_54 "3号CSC总压";
CM_ SG_ 2400710262 S2P_Detail_UCSC4_54 "4号CSC总压";
CM_ SG_ 2400710262 S2P_Detail_UCSC5_54 "5号CSC总压";
CM_ SG_ 2400710262 S2P_Detail_Reserved_54 "预留";
CM_ SG_ 2400710263 S2P_Detail_UCSC1_55 "1号CSC总压";
CM_ SG_ 2400710263 S2P_Detail_UCSC2_55 "2号CSC总压";
CM_ SG_ 2400710263 S2P_Detail_UCSC3_55 "3号CSC总压";
CM_ SG_ 2400710263 S2P_Detail_UCSC4_55 "4号CSC总压";
CM_ SG_ 2400710263 S2P_Detail_UCSC5_55 "5号CSC总压";
CM_ SG_ 2400710263 S2P_Detail_Reserved_55 "预留";
CM_ SG_ 2400710264 S2P_Detail_UCSC1_56 "1号CSC总压";
CM_ SG_ 2400710264 S2P_Detail_UCSC2_56 "2号CSC总压";
CM_ SG_ 2400710264 S2P_Detail_UCSC3_56 "3号CSC总压";
CM_ SG_ 2400710264 S2P_Detail_UCSC4_56 "4号CSC总压";
CM_ SG_ 2400710264 S2P_Detail_UCSC5_56 "5号CSC总压";
CM_ SG_ 2400710264 S2P_Detail_Reserved_56 "预留";
CM_ SG_ 2400710265 S2P_Detail_UCSC1_57 "1号CSC总压";
CM_ SG_ 2400710265 S2P_Detail_UCSC2_57 "2号CSC总压";
CM_ SG_ 2400710265 S2P_Detail_UCSC3_57 "3号CSC总压";
CM_ SG_ 2400710265 S2P_Detail_UCSC4_57 "4号CSC总压";
CM_ SG_ 2400710265 S2P_Detail_UCSC5_57 "5号CSC总压";
CM_ SG_ 2400710265 S2P_Detail_Reserved_57 "预留";
CM_ SG_ 2400710266 S2P_Detail_UCSC1_58 "1号CSC总压";
CM_ SG_ 2400710266 S2P_Detail_UCSC2_58 "2号CSC总压";
CM_ SG_ 2400710266 S2P_Detail_UCSC3_58 "3号CSC总压";
CM_ SG_ 2400710266 S2P_Detail_UCSC4_58 "4号CSC总压";
CM_ SG_ 2400710266 S2P_Detail_UCSC5_58 "5号CSC总压";
CM_ SG_ 2400710266 S2P_Detail_Reserved_58 "预留";
CM_ SG_ 2400710267 S2P_Detail_UCSC1_59 "1号CSC总压";
CM_ SG_ 2400710267 S2P_Detail_UCSC2_59 "2号CSC总压";
CM_ SG_ 2400710267 S2P_Detail_UCSC3_59 "3号CSC总压";
CM_ SG_ 2400710267 S2P_Detail_UCSC4_59 "4号CSC总压";
CM_ SG_ 2400710267 S2P_Detail_UCSC5_59 "5号CSC总压";
CM_ SG_ 2400710267 S2P_Detail_Reserved_59 "预留";
CM_ SG_ 2400710268 S2P_Detail_UCSC1_60 "1号CSC总压";
CM_ SG_ 2400710268 S2P_Detail_UCSC2_60 "2号CSC总压";
CM_ SG_ 2400710268 S2P_Detail_UCSC3_60 "3号CSC总压";
CM_ SG_ 2400710268 S2P_Detail_UCSC4_60 "4号CSC总压";
CM_ SG_ 2400710268 S2P_Detail_UCSC5_60 "5号CSC总压";
CM_ SG_ 2400710268 S2P_Detail_Reserved_60 "预留";
CM_ SG_ 2400710269 S2P_Detail_UCSC1_61 "1号CSC总压";
CM_ SG_ 2400710269 S2P_Detail_UCSC2_61 "2号CSC总压";
CM_ SG_ 2400710269 S2P_Detail_UCSC3_61 "3号CSC总压";
CM_ SG_ 2400710269 S2P_Detail_UCSC4_61 "4号CSC总压";
CM_ SG_ 2400710269 S2P_Detail_UCSC5_61 "5号CSC总压";
CM_ SG_ 2400710269 S2P_Detail_Reserved_61 "预留";
CM_ SG_ 2400710270 S2P_Detail_UCSC1_62 "1号CSC总压";
CM_ SG_ 2400710270 S2P_Detail_UCSC2_62 "2号CSC总压";
CM_ SG_ 2400710270 S2P_Detail_UCSC3_62 "3号CSC总压";
CM_ SG_ 2400710270 S2P_Detail_UCSC4_62 "4号CSC总压";
CM_ SG_ 2400710270 S2P_Detail_UCSC5_62 "5号CSC总压";
CM_ SG_ 2400710270 S2P_Detail_Reserved_62 "预留";
CM_ SG_ 2400710271 S2P_Detail_UCSC1_63 "1号CSC总压";
CM_ SG_ 2400710271 S2P_Detail_UCSC2_63 "2号CSC总压";
CM_ SG_ 2400710271 S2P_Detail_UCSC3_63 "3号CSC总压";
CM_ SG_ 2400710271 S2P_Detail_UCSC4_63 "4号CSC总压";
CM_ SG_ 2400710271 S2P_Detail_UCSC5_63 "5号CSC总压";
CM_ SG_ 2400710271 S2P_Detail_Reserved_63 "预留";
CM_ SG_ 2400775745 S2P_Detail_UCSC6_01 "6号CSC总压";
CM_ SG_ 2400775745 S2P_Detail_UCSC7_01 "7号CSC总压";
CM_ SG_ 2400775745 S2P_Detail_UCSC8_01 "8号CSC总压";
CM_ SG_ 2400775745 S2P_Detail_Reserved_01 "预留";
CM_ SG_ 2400775746 S2P_Detail_UCSC6_02 "6号CSC总压";
CM_ SG_ 2400775746 S2P_Detail_UCSC7_02 "7号CSC总压";
CM_ SG_ 2400775746 S2P_Detail_UCSC8_02 "8号CSC总压";
CM_ SG_ 2400775746 S2P_Detail_Reserved_02 "预留";
CM_ SG_ 2400775747 S2P_Detail_UCSC6_03 "6号CSC总压";
CM_ SG_ 2400775747 S2P_Detail_UCSC7_03 "7号CSC总压";
CM_ SG_ 2400775747 S2P_Detail_UCSC8_03 "8号CSC总压";
CM_ SG_ 2400775747 S2P_Detail_Reserved_03 "预留";
CM_ SG_ 2400775748 S2P_Detail_UCSC6_04 "6号CSC总压";
CM_ SG_ 2400775748 S2P_Detail_UCSC7_04 "7号CSC总压";
CM_ SG_ 2400775748 S2P_Detail_UCSC8_04 "8号CSC总压";
CM_ SG_ 2400775748 S2P_Detail_Reserved_04 "预留";
CM_ SG_ 2400775749 S2P_Detail_UCSC6_05 "6号CSC总压";
CM_ SG_ 2400775749 S2P_Detail_UCSC7_05 "7号CSC总压";
CM_ SG_ 2400775749 S2P_Detail_UCSC8_05 "8号CSC总压";
CM_ SG_ 2400775749 S2P_Detail_Reserved_05 "预留";
CM_ SG_ 2400775750 S2P_Detail_UCSC6_06 "6号CSC总压";
CM_ SG_ 2400775750 S2P_Detail_UCSC7_06 "7号CSC总压";
CM_ SG_ 2400775750 S2P_Detail_UCSC8_06 "8号CSC总压";
CM_ SG_ 2400775750 S2P_Detail_Reserved_06 "预留";
CM_ SG_ 2400775751 S2P_Detail_UCSC6_07 "6号CSC总压";
CM_ SG_ 2400775751 S2P_Detail_UCSC7_07 "7号CSC总压";
CM_ SG_ 2400775751 S2P_Detail_UCSC8_07 "8号CSC总压";
CM_ SG_ 2400775751 S2P_Detail_Reserved_07 "预留";
CM_ SG_ 2400775752 S2P_Detail_UCSC6_08 "6号CSC总压";
CM_ SG_ 2400775752 S2P_Detail_UCSC7_08 "7号CSC总压";
CM_ SG_ 2400775752 S2P_Detail_UCSC8_08 "8号CSC总压";
CM_ SG_ 2400775752 S2P_Detail_Reserved_08 "预留";
CM_ SG_ 2400775753 S2P_Detail_UCSC6_09 "6号CSC总压";
CM_ SG_ 2400775753 S2P_Detail_UCSC7_09 "7号CSC总压";
CM_ SG_ 2400775753 S2P_Detail_UCSC8_09 "8号CSC总压";
CM_ SG_ 2400775753 S2P_Detail_Reserved_09 "预留";
CM_ SG_ 2400775754 S2P_Detail_UCSC6_10 "6号CSC总压";
CM_ SG_ 2400775754 S2P_Detail_UCSC7_10 "7号CSC总压";
CM_ SG_ 2400775754 S2P_Detail_UCSC8_10 "8号CSC总压";
CM_ SG_ 2400775754 S2P_Detail_Reserved_10 "预留";
CM_ SG_ 2400775755 S2P_Detail_UCSC6_11 "6号CSC总压";
CM_ SG_ 2400775755 S2P_Detail_UCSC7_11 "7号CSC总压";
CM_ SG_ 2400775755 S2P_Detail_UCSC8_11 "8号CSC总压";
CM_ SG_ 2400775755 S2P_Detail_Reserved_11 "预留";
CM_ SG_ 2400775756 S2P_Detail_UCSC6_12 "6号CSC总压";
CM_ SG_ 2400775756 S2P_Detail_UCSC7_12 "7号CSC总压";
CM_ SG_ 2400775756 S2P_Detail_UCSC8_12 "8号CSC总压";
CM_ SG_ 2400775756 S2P_Detail_Reserved_12 "预留";
CM_ SG_ 2400775757 S2P_Detail_UCSC6_13 "6号CSC总压";
CM_ SG_ 2400775757 S2P_Detail_UCSC7_13 "7号CSC总压";
CM_ SG_ 2400775757 S2P_Detail_UCSC8_13 "8号CSC总压";
CM_ SG_ 2400775757 S2P_Detail_Reserved_13 "预留";
CM_ SG_ 2400775758 S2P_Detail_UCSC6_14 "6号CSC总压";
CM_ SG_ 2400775758 S2P_Detail_UCSC7_14 "7号CSC总压";
CM_ SG_ 2400775758 S2P_Detail_UCSC8_14 "8号CSC总压";
CM_ SG_ 2400775758 S2P_Detail_Reserved_14 "预留";
CM_ SG_ 2400775759 S2P_Detail_UCSC6_15 "6号CSC总压";
CM_ SG_ 2400775759 S2P_Detail_UCSC7_15 "7号CSC总压";
CM_ SG_ 2400775759 S2P_Detail_UCSC8_15 "8号CSC总压";
CM_ SG_ 2400775759 S2P_Detail_Reserved_15 "预留";
CM_ SG_ 2400775760 S2P_Detail_UCSC6_16 "6号CSC总压";
CM_ SG_ 2400775760 S2P_Detail_UCSC7_16 "7号CSC总压";
CM_ SG_ 2400775760 S2P_Detail_UCSC8_16 "8号CSC总压";
CM_ SG_ 2400775760 S2P_Detail_Reserved_16 "预留";
CM_ SG_ 2400775761 S2P_Detail_UCSC6_17 "6号CSC总压";
CM_ SG_ 2400775761 S2P_Detail_UCSC7_17 "7号CSC总压";
CM_ SG_ 2400775761 S2P_Detail_UCSC8_17 "8号CSC总压";
CM_ SG_ 2400775761 S2P_Detail_Reserved_17 "预留";
CM_ SG_ 2400775762 S2P_Detail_UCSC6_18 "6号CSC总压";
CM_ SG_ 2400775762 S2P_Detail_UCSC7_18 "7号CSC总压";
CM_ SG_ 2400775762 S2P_Detail_UCSC8_18 "8号CSC总压";
CM_ SG_ 2400775762 S2P_Detail_Reserved_18 "预留";
CM_ SG_ 2400775763 S2P_Detail_UCSC6_19 "6号CSC总压";
CM_ SG_ 2400775763 S2P_Detail_UCSC7_19 "7号CSC总压";
CM_ SG_ 2400775763 S2P_Detail_UCSC8_19 "8号CSC总压";
CM_ SG_ 2400775763 S2P_Detail_Reserved_19 "预留";
CM_ SG_ 2400775764 S2P_Detail_UCSC6_20 "6号CSC总压";
CM_ SG_ 2400775764 S2P_Detail_UCSC7_20 "7号CSC总压";
CM_ SG_ 2400775764 S2P_Detail_UCSC8_20 "8号CSC总压";
CM_ SG_ 2400775764 S2P_Detail_Reserved_20 "预留";
CM_ SG_ 2400775765 S2P_Detail_UCSC6_21 "6号CSC总压";
CM_ SG_ 2400775765 S2P_Detail_UCSC7_21 "7号CSC总压";
CM_ SG_ 2400775765 S2P_Detail_UCSC8_21 "8号CSC总压";
CM_ SG_ 2400775765 S2P_Detail_Reserved_21 "预留";
CM_ SG_ 2400775766 S2P_Detail_UCSC6_22 "6号CSC总压";
CM_ SG_ 2400775766 S2P_Detail_UCSC7_22 "7号CSC总压";
CM_ SG_ 2400775766 S2P_Detail_UCSC8_22 "8号CSC总压";
CM_ SG_ 2400775766 S2P_Detail_Reserved_22 "预留";
CM_ SG_ 2400775767 S2P_Detail_UCSC6_23 "6号CSC总压";
CM_ SG_ 2400775767 S2P_Detail_UCSC7_23 "7号CSC总压";
CM_ SG_ 2400775767 S2P_Detail_UCSC8_23 "8号CSC总压";
CM_ SG_ 2400775767 S2P_Detail_Reserved_23 "预留";
CM_ SG_ 2400775768 S2P_Detail_UCSC6_24 "6号CSC总压";
CM_ SG_ 2400775768 S2P_Detail_UCSC7_24 "7号CSC总压";
CM_ SG_ 2400775768 S2P_Detail_UCSC8_24 "8号CSC总压";
CM_ SG_ 2400775768 S2P_Detail_Reserved_24 "预留";
CM_ SG_ 2400775769 S2P_Detail_UCSC6_25 "6号CSC总压";
CM_ SG_ 2400775769 S2P_Detail_UCSC7_25 "7号CSC总压";
CM_ SG_ 2400775769 S2P_Detail_UCSC8_25 "8号CSC总压";
CM_ SG_ 2400775769 S2P_Detail_Reserved_25 "预留";
CM_ SG_ 2400775770 S2P_Detail_UCSC6_26 "6号CSC总压";
CM_ SG_ 2400775770 S2P_Detail_UCSC7_26 "7号CSC总压";
CM_ SG_ 2400775770 S2P_Detail_UCSC8_26 "8号CSC总压";
CM_ SG_ 2400775770 S2P_Detail_Reserved_26 "预留";
CM_ SG_ 2400775771 S2P_Detail_UCSC6_27 "6号CSC总压";
CM_ SG_ 2400775771 S2P_Detail_UCSC7_27 "7号CSC总压";
CM_ SG_ 2400775771 S2P_Detail_UCSC8_27 "8号CSC总压";
CM_ SG_ 2400775771 S2P_Detail_Reserved_27 "预留";
CM_ SG_ 2400775772 S2P_Detail_UCSC6_28 "6号CSC总压";
CM_ SG_ 2400775772 S2P_Detail_UCSC7_28 "7号CSC总压";
CM_ SG_ 2400775772 S2P_Detail_UCSC8_28 "8号CSC总压";
CM_ SG_ 2400775772 S2P_Detail_Reserved_28 "预留";
CM_ SG_ 2400775773 S2P_Detail_UCSC6_29 "6号CSC总压";
CM_ SG_ 2400775773 S2P_Detail_UCSC7_29 "7号CSC总压";
CM_ SG_ 2400775773 S2P_Detail_UCSC8_29 "8号CSC总压";
CM_ SG_ 2400775773 S2P_Detail_Reserved_29 "预留";
CM_ SG_ 2400775774 S2P_Detail_UCSC6_30 "6号CSC总压";
CM_ SG_ 2400775774 S2P_Detail_UCSC7_30 "7号CSC总压";
CM_ SG_ 2400775774 S2P_Detail_UCSC8_30 "8号CSC总压";
CM_ SG_ 2400775774 S2P_Detail_Reserved_30 "预留";
CM_ SG_ 2400775775 S2P_Detail_UCSC6_31 "6号CSC总压";
CM_ SG_ 2400775775 S2P_Detail_UCSC7_31 "7号CSC总压";
CM_ SG_ 2400775775 S2P_Detail_UCSC8_31 "8号CSC总压";
CM_ SG_ 2400775775 S2P_Detail_Reserved_31 "预留";
CM_ SG_ 2400775776 S2P_Detail_UCSC6_32 "6号CSC总压";
CM_ SG_ 2400775776 S2P_Detail_UCSC7_32 "7号CSC总压";
CM_ SG_ 2400775776 S2P_Detail_UCSC8_32 "8号CSC总压";
CM_ SG_ 2400775776 S2P_Detail_Reserved_32 "预留";
CM_ SG_ 2400775777 S2P_Detail_UCSC6_33 "6号CSC总压";
CM_ SG_ 2400775777 S2P_Detail_UCSC7_33 "7号CSC总压";
CM_ SG_ 2400775777 S2P_Detail_UCSC8_33 "8号CSC总压";
CM_ SG_ 2400775777 S2P_Detail_Reserved_33 "预留";
CM_ SG_ 2400775778 S2P_Detail_UCSC6_34 "6号CSC总压";
CM_ SG_ 2400775778 S2P_Detail_UCSC7_34 "7号CSC总压";
CM_ SG_ 2400775778 S2P_Detail_UCSC8_34 "8号CSC总压";
CM_ SG_ 2400775778 S2P_Detail_Reserved_34 "预留";
CM_ SG_ 2400775779 S2P_Detail_UCSC6_35 "6号CSC总压";
CM_ SG_ 2400775779 S2P_Detail_UCSC7_35 "7号CSC总压";
CM_ SG_ 2400775779 S2P_Detail_UCSC8_35 "8号CSC总压";
CM_ SG_ 2400775779 S2P_Detail_Reserved_35 "预留";
CM_ SG_ 2400775780 S2P_Detail_UCSC6_36 "6号CSC总压";
CM_ SG_ 2400775780 S2P_Detail_UCSC7_36 "7号CSC总压";
CM_ SG_ 2400775780 S2P_Detail_UCSC8_36 "8号CSC总压";
CM_ SG_ 2400775780 S2P_Detail_Reserved_36 "预留";
CM_ SG_ 2400775781 S2P_Detail_UCSC6_37 "6号CSC总压";
CM_ SG_ 2400775781 S2P_Detail_UCSC7_37 "7号CSC总压";
CM_ SG_ 2400775781 S2P_Detail_UCSC8_37 "8号CSC总压";
CM_ SG_ 2400775781 S2P_Detail_Reserved_37 "预留";
CM_ SG_ 2400775782 S2P_Detail_UCSC6_38 "6号CSC总压";
CM_ SG_ 2400775782 S2P_Detail_UCSC7_38 "7号CSC总压";
CM_ SG_ 2400775782 S2P_Detail_UCSC8_38 "8号CSC总压";
CM_ SG_ 2400775782 S2P_Detail_Reserved_38 "预留";
CM_ SG_ 2400775783 S2P_Detail_UCSC6_39 "6号CSC总压";
CM_ SG_ 2400775783 S2P_Detail_UCSC7_39 "7号CSC总压";
CM_ SG_ 2400775783 S2P_Detail_UCSC8_39 "8号CSC总压";
CM_ SG_ 2400775783 S2P_Detail_Reserved_39 "预留";
CM_ SG_ 2400775784 S2P_Detail_UCSC6_40 "6号CSC总压";
CM_ SG_ 2400775784 S2P_Detail_UCSC7_40 "7号CSC总压";
CM_ SG_ 2400775784 S2P_Detail_UCSC8_40 "8号CSC总压";
CM_ SG_ 2400775784 S2P_Detail_Reserved_40 "预留";
CM_ SG_ 2400775785 S2P_Detail_UCSC6_41 "6号CSC总压";
CM_ SG_ 2400775785 S2P_Detail_UCSC7_41 "7号CSC总压";
CM_ SG_ 2400775785 S2P_Detail_UCSC8_41 "8号CSC总压";
CM_ SG_ 2400775785 S2P_Detail_Reserved_41 "预留";
CM_ SG_ 2400775786 S2P_Detail_UCSC6_42 "6号CSC总压";
CM_ SG_ 2400775786 S2P_Detail_UCSC7_42 "7号CSC总压";
CM_ SG_ 2400775786 S2P_Detail_UCSC8_42 "8号CSC总压";
CM_ SG_ 2400775786 S2P_Detail_Reserved_42 "预留";
CM_ SG_ 2400775787 S2P_Detail_UCSC6_43 "6号CSC总压";
CM_ SG_ 2400775787 S2P_Detail_UCSC7_43 "7号CSC总压";
CM_ SG_ 2400775787 S2P_Detail_UCSC8_43 "8号CSC总压";
CM_ SG_ 2400775787 S2P_Detail_Reserved_43 "预留";
CM_ SG_ 2400775788 S2P_Detail_UCSC6_44 "6号CSC总压";
CM_ SG_ 2400775788 S2P_Detail_UCSC7_44 "7号CSC总压";
CM_ SG_ 2400775788 S2P_Detail_UCSC8_44 "8号CSC总压";
CM_ SG_ 2400775788 S2P_Detail_Reserved_44 "预留";
CM_ SG_ 2400775789 S2P_Detail_UCSC6_45 "6号CSC总压";
CM_ SG_ 2400775789 S2P_Detail_UCSC7_45 "7号CSC总压";
CM_ SG_ 2400775789 S2P_Detail_UCSC8_45 "8号CSC总压";
CM_ SG_ 2400775789 S2P_Detail_Reserved_45 "预留";
CM_ SG_ 2400775790 S2P_Detail_UCSC6_46 "6号CSC总压";
CM_ SG_ 2400775790 S2P_Detail_UCSC7_46 "7号CSC总压";
CM_ SG_ 2400775790 S2P_Detail_UCSC8_46 "8号CSC总压";
CM_ SG_ 2400775790 S2P_Detail_Reserved_46 "预留";
CM_ SG_ 2400775791 S2P_Detail_UCSC6_47 "6号CSC总压";
CM_ SG_ 2400775791 S2P_Detail_UCSC7_47 "7号CSC总压";
CM_ SG_ 2400775791 S2P_Detail_UCSC8_47 "8号CSC总压";
CM_ SG_ 2400775791 S2P_Detail_Reserved_47 "预留";
CM_ SG_ 2400775792 S2P_Detail_UCSC6_48 "6号CSC总压";
CM_ SG_ 2400775792 S2P_Detail_UCSC7_48 "7号CSC总压";
CM_ SG_ 2400775792 S2P_Detail_UCSC8_48 "8号CSC总压";
CM_ SG_ 2400775792 S2P_Detail_Reserved_48 "预留";
CM_ SG_ 2400775793 S2P_Detail_UCSC6_49 "6号CSC总压";
CM_ SG_ 2400775793 S2P_Detail_UCSC7_49 "7号CSC总压";
CM_ SG_ 2400775793 S2P_Detail_UCSC8_49 "8号CSC总压";
CM_ SG_ 2400775793 S2P_Detail_Reserved_49 "预留";
CM_ SG_ 2400775794 S2P_Detail_UCSC6_50 "6号CSC总压";
CM_ SG_ 2400775794 S2P_Detail_UCSC7_50 "7号CSC总压";
CM_ SG_ 2400775794 S2P_Detail_UCSC8_50 "8号CSC总压";
CM_ SG_ 2400775794 S2P_Detail_Reserved_50 "预留";
CM_ SG_ 2400775795 S2P_Detail_UCSC6_51 "6号CSC总压";
CM_ SG_ 2400775795 S2P_Detail_UCSC7_51 "7号CSC总压";
CM_ SG_ 2400775795 S2P_Detail_UCSC8_51 "8号CSC总压";
CM_ SG_ 2400775795 S2P_Detail_Reserved_51 "预留";
CM_ SG_ 2400775796 S2P_Detail_UCSC6_52 "6号CSC总压";
CM_ SG_ 2400775796 S2P_Detail_UCSC7_52 "7号CSC总压";
CM_ SG_ 2400775796 S2P_Detail_UCSC8_52 "8号CSC总压";
CM_ SG_ 2400775796 S2P_Detail_Reserved_52 "预留";
CM_ SG_ 2400775797 S2P_Detail_UCSC6_53 "6号CSC总压";
CM_ SG_ 2400775797 S2P_Detail_UCSC7_53 "7号CSC总压";
CM_ SG_ 2400775797 S2P_Detail_UCSC8_53 "8号CSC总压";
CM_ SG_ 2400775797 S2P_Detail_Reserved_53 "预留";
CM_ SG_ 2400775798 S2P_Detail_UCSC6_54 "6号CSC总压";
CM_ SG_ 2400775798 S2P_Detail_UCSC7_54 "7号CSC总压";
CM_ SG_ 2400775798 S2P_Detail_UCSC8_54 "8号CSC总压";
CM_ SG_ 2400775798 S2P_Detail_Reserved_54 "预留";
CM_ SG_ 2400775799 S2P_Detail_UCSC6_55 "6号CSC总压";
CM_ SG_ 2400775799 S2P_Detail_UCSC7_55 "7号CSC总压";
CM_ SG_ 2400775799 S2P_Detail_UCSC8_55 "8号CSC总压";
CM_ SG_ 2400775799 S2P_Detail_Reserved_55 "预留";
CM_ SG_ 2400775800 S2P_Detail_UCSC6_56 "6号CSC总压";
CM_ SG_ 2400775800 S2P_Detail_UCSC7_56 "7号CSC总压";
CM_ SG_ 2400775800 S2P_Detail_UCSC8_56 "8号CSC总压";
CM_ SG_ 2400775800 S2P_Detail_Reserved_56 "预留";
CM_ SG_ 2400775801 S2P_Detail_UCSC6_57 "6号CSC总压";
CM_ SG_ 2400775801 S2P_Detail_UCSC7_57 "7号CSC总压";
CM_ SG_ 2400775801 S2P_Detail_UCSC8_57 "8号CSC总压";
CM_ SG_ 2400775801 S2P_Detail_Reserved_57 "预留";
CM_ SG_ 2400775802 S2P_Detail_UCSC6_58 "6号CSC总压";
CM_ SG_ 2400775802 S2P_Detail_UCSC7_58 "7号CSC总压";
CM_ SG_ 2400775802 S2P_Detail_UCSC8_58 "8号CSC总压";
CM_ SG_ 2400775802 S2P_Detail_Reserved_58 "预留";
CM_ SG_ 2400775803 S2P_Detail_UCSC6_59 "6号CSC总压";
CM_ SG_ 2400775803 S2P_Detail_UCSC7_59 "7号CSC总压";
CM_ SG_ 2400775803 S2P_Detail_UCSC8_59 "8号CSC总压";
CM_ SG_ 2400775803 S2P_Detail_Reserved_59 "预留";
CM_ SG_ 2400775804 S2P_Detail_UCSC6_60 "6号CSC总压";
CM_ SG_ 2400775804 S2P_Detail_UCSC7_60 "7号CSC总压";
CM_ SG_ 2400775804 S2P_Detail_UCSC8_60 "8号CSC总压";
CM_ SG_ 2400775804 S2P_Detail_Reserved_60 "预留";
CM_ SG_ 2400775805 S2P_Detail_UCSC6_61 "6号CSC总压";
CM_ SG_ 2400775805 S2P_Detail_UCSC7_61 "7号CSC总压";
CM_ SG_ 2400775805 S2P_Detail_UCSC8_61 "8号CSC总压";
CM_ SG_ 2400775805 S2P_Detail_Reserved_61 "预留";
CM_ SG_ 2400775806 S2P_Detail_UCSC6_62 "6号CSC总压";
CM_ SG_ 2400775806 S2P_Detail_UCSC7_62 "7号CSC总压";
CM_ SG_ 2400775806 S2P_Detail_UCSC8_62 "8号CSC总压";
CM_ SG_ 2400775806 S2P_Detail_Reserved_62 "预留";
CM_ SG_ 2400775807 S2P_Detail_UCSC6_63 "6号CSC总压";
CM_ SG_ 2400775807 S2P_Detail_UCSC7_63 "7号CSC总压";
CM_ SG_ 2400775807 S2P_Detail_UCSC8_63 "8号CSC总压";
CM_ SG_ 2400775807 S2P_Detail_Reserved_63 "预留";
CM_ SG_ 2333208209 M2P_SUMDATA1_CUS_Reserved1_01 "MBMU客户预留信号";
CM_ SG_ 2333208210 M2P_SUMDATA1_CUS_Reserved1_02 "MBMU客户预留信号";
CM_ SG_ 2333208211 M2P_SUMDATA1_CUS_Reserved1_03 "MBMU客户预留信号";
CM_ SG_ 2333208212 M2P_SUMDATA1_CUS_Reserved1_04 "MBMU客户预留信号";
CM_ SG_ 2333208213 M2P_SUMDATA1_CUS_Reserved1_05 "MBMU客户预留信号";
CM_ SG_ 2333208214 M2P_SUMDATA1_CUS_Reserved1_06 "MBMU客户预留信号";
CM_ SG_ 2333208215 M2P_SUMDATA1_CUS_Reserved1_07 "MBMU客户预留信号";
CM_ SG_ 2333208216 M2P_SUMDATA1_CUS_Reserved1_08 "MBMU客户预留信号";
CM_ SG_ 2333208217 M2P_SUMDATA1_CUS_Reserved1_09 "MBMU客户预留信号";
CM_ SG_ 2333208218 M2P_SUMDATA1_CUS_Reserved1_10 "MBMU客户预留信号";
CM_ SG_ 2333208219 M2P_SUMDATA1_CUS_Reserved1_11 "MBMU客户预留信号";
CM_ SG_ 2333208220 M2P_SUMDATA1_CUS_Reserved1_12 "MBMU客户预留信号";
CM_ SG_ 2333208221 M2P_SUMDATA1_CUS_Reserved1_13 "MBMU客户预留信号";
CM_ SG_ 2333208222 M2P_SUMDATA1_CUS_Reserved1_14 "MBMU客户预留信号";
CM_ SG_ 2333208223 M2P_SUMDATA1_CUS_Reserved1_15 "MBMU客户预留信号";
CM_ SG_ 2333208224 M2P_SUMDATA1_CUS_Reserved1_16 "MBMU客户预留信号";
CM_ SG_ 2333208225 M2P_SUMDATA1_CUS_Reserved1_17 "MBMU客户预留信号";
CM_ SG_ 2333208226 M2P_SUMDATA1_CUS_Reserved1_18 "MBMU客户预留信号";
CM_ SG_ 2333208227 M2P_SUMDATA1_CUS_Reserved1_19 "MBMU客户预留信号";
CM_ SG_ 2333208228 M2P_SUMDATA1_CUS_Reserved1_20 "MBMU客户预留信号";
CM_ SG_ 2333208229 M2P_SUMDATA1_CUS_Reserved1_21 "MBMU客户预留信号";
CM_ SG_ 2333208230 M2P_SUMDATA1_CUS_Reserved1_22 "MBMU客户预留信号";
CM_ SG_ 2333208231 M2P_SUMDATA1_CUS_Reserved1_23 "MBMU客户预留信号";
CM_ SG_ 2333208232 M2P_SUMDATA1_CUS_Reserved1_24 "MBMU客户预留信号";
CM_ SG_ 2333208233 M2P_SUMDATA1_CUS_Reserved1_25 "MBMU客户预留信号";
CM_ SG_ 2333208234 M2P_SUMDATA1_CUS_Reserved1_26 "MBMU客户预留信号";
CM_ SG_ 2333208235 M2P_SUMDATA1_CUS_Reserved1_27 "MBMU客户预留信号";
CM_ SG_ 2333208236 M2P_SUMDATA1_CUS_Reserved1_28 "MBMU客户预留信号";
CM_ SG_ 2333208237 M2P_SUMDATA1_CUS_Reserved1_29 "MBMU客户预留信号";
CM_ SG_ 2333208238 M2P_SUMDATA1_CUS_Reserved1_30 "MBMU客户预留信号";
CM_ SG_ 2333208239 M2P_SUMDATA1_CUS_Reserved1_31 "MBMU客户预留信号";
CM_ SG_ 2333273745 M2P_SUMDATA2_CUS_Reserved2_01 "MBMU客户预留信号";
CM_ SG_ 2333273746 M2P_SUMDATA2_CUS_Reserved2_02 "MBMU客户预留信号";
CM_ SG_ 2333273747 M2P_SUMDATA2_CUS_Reserved2_03 "MBMU客户预留信号";
CM_ SG_ 2333273748 M2P_SUMDATA2_CUS_Reserved2_04 "MBMU客户预留信号";
CM_ SG_ 2333273749 M2P_SUMDATA2_CUS_Reserved2_05 "MBMU客户预留信号";
CM_ SG_ 2333273750 M2P_SUMDATA2_CUS_Reserved2_06 "MBMU客户预留信号";
CM_ SG_ 2333273751 M2P_SUMDATA2_CUS_Reserved2_07 "MBMU客户预留信号";
CM_ SG_ 2333273752 M2P_SUMDATA2_CUS_Reserved2_08 "MBMU客户预留信号";
CM_ SG_ 2333273753 M2P_SUMDATA2_CUS_Reserved2_09 "MBMU客户预留信号";
CM_ SG_ 2333273754 M2P_SUMDATA2_CUS_Reserved2_10 "MBMU客户预留信号";
CM_ SG_ 2333273755 M2P_SUMDATA2_CUS_Reserved2_11 "MBMU客户预留信号";
CM_ SG_ 2333273756 M2P_SUMDATA2_CUS_Reserved2_12 "MBMU客户预留信号";
CM_ SG_ 2333273757 M2P_SUMDATA2_CUS_Reserved2_13 "MBMU客户预留信号";
CM_ SG_ 2333273758 M2P_SUMDATA2_CUS_Reserved2_14 "MBMU客户预留信号";
CM_ SG_ 2333273759 M2P_SUMDATA2_CUS_Reserved2_15 "MBMU客户预留信号";
CM_ SG_ 2333273760 M2P_SUMDATA2_CUS_Reserved2_16 "MBMU客户预留信号";
CM_ SG_ 2333273761 M2P_SUMDATA2_CUS_Reserved2_17 "MBMU客户预留信号";
CM_ SG_ 2333273762 M2P_SUMDATA2_CUS_Reserved2_18 "MBMU客户预留信号";
CM_ SG_ 2333273763 M2P_SUMDATA2_CUS_Reserved2_19 "MBMU客户预留信号";
CM_ SG_ 2333273764 M2P_SUMDATA2_CUS_Reserved2_20 "MBMU客户预留信号";
CM_ SG_ 2333273765 M2P_SUMDATA2_CUS_Reserved2_21 "MBMU客户预留信号";
CM_ SG_ 2333273766 M2P_SUMDATA2_CUS_Reserved2_22 "MBMU客户预留信号";
CM_ SG_ 2333273767 M2P_SUMDATA2_CUS_Reserved2_23 "MBMU客户预留信号";
CM_ SG_ 2333273768 M2P_SUMDATA2_CUS_Reserved2_24 "MBMU客户预留信号";
CM_ SG_ 2333273769 M2P_SUMDATA2_CUS_Reserved2_25 "MBMU客户预留信号";
CM_ SG_ 2333273770 M2P_SUMDATA2_CUS_Reserved2_26 "MBMU客户预留信号";
CM_ SG_ 2333273771 M2P_SUMDATA2_CUS_Reserved2_27 "MBMU客户预留信号";
CM_ SG_ 2333273772 M2P_SUMDATA2_CUS_Reserved2_28 "MBMU客户预留信号";
CM_ SG_ 2333273773 M2P_SUMDATA2_CUS_Reserved2_29 "MBMU客户预留信号";
CM_ SG_ 2333273774 M2P_SUMDATA2_CUS_Reserved2_30 "MBMU客户预留信号";
CM_ SG_ 2333273775 M2P_SUMDATA2_CUS_Reserved2_31 "MBMU客户预留信号";
CM_ SG_ 2333339281 M2P_SUMDATA3_CUS_Reserved3_01 "MBMU客户预留信号";
CM_ SG_ 2333339282 M2P_SUMDATA3_CUS_Reserved3_02 "MBMU客户预留信号";
CM_ SG_ 2333339283 M2P_SUMDATA3_CUS_Reserved3_03 "MBMU客户预留信号";
CM_ SG_ 2333339284 M2P_SUMDATA3_CUS_Reserved3_04 "MBMU客户预留信号";
CM_ SG_ 2333339285 M2P_SUMDATA3_CUS_Reserved3_05 "MBMU客户预留信号";
CM_ SG_ 2333339286 M2P_SUMDATA3_CUS_Reserved3_06 "MBMU客户预留信号";
CM_ SG_ 2333339287 M2P_SUMDATA3_CUS_Reserved3_07 "MBMU客户预留信号";
CM_ SG_ 2333339288 M2P_SUMDATA3_CUS_Reserved3_08 "MBMU客户预留信号";
CM_ SG_ 2333339289 M2P_SUMDATA3_CUS_Reserved3_09 "MBMU客户预留信号";
CM_ SG_ 2333339290 M2P_SUMDATA3_CUS_Reserved3_10 "MBMU客户预留信号";
CM_ SG_ 2333339291 M2P_SUMDATA3_CUS_Reserved3_11 "MBMU客户预留信号";
CM_ SG_ 2333339292 M2P_SUMDATA3_CUS_Reserved3_12 "MBMU客户预留信号";
CM_ SG_ 2333339293 M2P_SUMDATA3_CUS_Reserved3_13 "MBMU客户预留信号";
CM_ SG_ 2333339294 M2P_SUMDATA3_CUS_Reserved3_14 "MBMU客户预留信号";
CM_ SG_ 2333339295 M2P_SUMDATA3_CUS_Reserved3_15 "MBMU客户预留信号";
CM_ SG_ 2333339296 M2P_SUMDATA3_CUS_Reserved3_16 "MBMU客户预留信号";
CM_ SG_ 2333339297 M2P_SUMDATA3_CUS_Reserved3_17 "MBMU客户预留信号";
CM_ SG_ 2333339298 M2P_SUMDATA3_CUS_Reserved3_18 "MBMU客户预留信号";
CM_ SG_ 2333339299 M2P_SUMDATA3_CUS_Reserved3_19 "MBMU客户预留信号";
CM_ SG_ 2333339300 M2P_SUMDATA3_CUS_Reserved3_20 "MBMU客户预留信号";
CM_ SG_ 2333339301 M2P_SUMDATA3_CUS_Reserved3_21 "MBMU客户预留信号";
CM_ SG_ 2333339302 M2P_SUMDATA3_CUS_Reserved3_22 "MBMU客户预留信号";
CM_ SG_ 2333339303 M2P_SUMDATA3_CUS_Reserved3_23 "MBMU客户预留信号";
CM_ SG_ 2333339304 M2P_SUMDATA3_CUS_Reserved3_24 "MBMU客户预留信号";
CM_ SG_ 2333339305 M2P_SUMDATA3_CUS_Reserved3_25 "MBMU客户预留信号";
CM_ SG_ 2333339306 M2P_SUMDATA3_CUS_Reserved3_26 "MBMU客户预留信号";
CM_ SG_ 2333339307 M2P_SUMDATA3_CUS_Reserved3_27 "MBMU客户预留信号";
CM_ SG_ 2333339308 M2P_SUMDATA3_CUS_Reserved3_28 "MBMU客户预留信号";
CM_ SG_ 2333339309 M2P_SUMDATA3_CUS_Reserved3_29 "MBMU客户预留信号";
CM_ SG_ 2333339310 M2P_SUMDATA3_CUS_Reserved3_30 "MBMU客户预留信号";
CM_ SG_ 2333339311 M2P_SUMDATA3_CUS_Reserved3_31 "MBMU客户预留信号";
CM_ SG_ 2333404817 M2P_SUMDATA4_CUS_Reserved4_01 "MBMU客户预留信号";
CM_ SG_ 2333404818 M2P_SUMDATA4_CUS_Reserved4_02 "MBMU客户预留信号";
CM_ SG_ 2333404819 M2P_SUMDATA4_CUS_Reserved4_03 "MBMU客户预留信号";
CM_ SG_ 2333404820 M2P_SUMDATA4_CUS_Reserved4_04 "MBMU客户预留信号";
CM_ SG_ 2333404821 M2P_SUMDATA4_CUS_Reserved4_05 "MBMU客户预留信号";
CM_ SG_ 2333404822 M2P_SUMDATA4_CUS_Reserved4_06 "MBMU客户预留信号";
CM_ SG_ 2333404823 M2P_SUMDATA4_CUS_Reserved4_07 "MBMU客户预留信号";
CM_ SG_ 2333404824 M2P_SUMDATA4_CUS_Reserved4_08 "MBMU客户预留信号";
CM_ SG_ 2333404825 M2P_SUMDATA4_CUS_Reserved4_09 "MBMU客户预留信号";
CM_ SG_ 2333404826 M2P_SUMDATA4_CUS_Reserved4_10 "MBMU客户预留信号";
CM_ SG_ 2333404827 M2P_SUMDATA4_CUS_Reserved4_11 "MBMU客户预留信号";
CM_ SG_ 2333404828 M2P_SUMDATA4_CUS_Reserved4_12 "MBMU客户预留信号";
CM_ SG_ 2333404829 M2P_SUMDATA4_CUS_Reserved4_13 "MBMU客户预留信号";
CM_ SG_ 2333404830 M2P_SUMDATA4_CUS_Reserved4_14 "MBMU客户预留信号";
CM_ SG_ 2333404831 M2P_SUMDATA4_CUS_Reserved4_15 "MBMU客户预留信号";
CM_ SG_ 2333404832 M2P_SUMDATA4_CUS_Reserved4_16 "MBMU客户预留信号";
CM_ SG_ 2333404833 M2P_SUMDATA4_CUS_Reserved4_17 "MBMU客户预留信号";
CM_ SG_ 2333404834 M2P_SUMDATA4_CUS_Reserved4_18 "MBMU客户预留信号";
CM_ SG_ 2333404835 M2P_SUMDATA4_CUS_Reserved4_19 "MBMU客户预留信号";
CM_ SG_ 2333404836 M2P_SUMDATA4_CUS_Reserved4_20 "MBMU客户预留信号";
CM_ SG_ 2333404837 M2P_SUMDATA4_CUS_Reserved4_21 "MBMU客户预留信号";
CM_ SG_ 2333404838 M2P_SUMDATA4_CUS_Reserved4_22 "MBMU客户预留信号";
CM_ SG_ 2333404839 M2P_SUMDATA4_CUS_Reserved4_23 "MBMU客户预留信号";
CM_ SG_ 2333404840 M2P_SUMDATA4_CUS_Reserved4_24 "MBMU客户预留信号";
CM_ SG_ 2333404841 M2P_SUMDATA4_CUS_Reserved4_25 "MBMU客户预留信号";
CM_ SG_ 2333404842 M2P_SUMDATA4_CUS_Reserved4_26 "MBMU客户预留信号";
CM_ SG_ 2333404843 M2P_SUMDATA4_CUS_Reserved4_27 "MBMU客户预留信号";
CM_ SG_ 2333404844 M2P_SUMDATA4_CUS_Reserved4_28 "MBMU客户预留信号";
CM_ SG_ 2333404845 M2P_SUMDATA4_CUS_Reserved4_29 "MBMU客户预留信号";
CM_ SG_ 2333404846 M2P_SUMDATA4_CUS_Reserved4_30 "MBMU客户预留信号";
CM_ SG_ 2333404847 M2P_SUMDATA4_CUS_Reserved4_31 "MBMU客户预留信号";
CM_ SG_ 2333470353 M2P_SUMDATA5_CUS_Reserved5_01 "MBMU客户预留信号";
CM_ SG_ 2333470354 M2P_SUMDATA5_CUS_Reserved5_02 "MBMU客户预留信号";
CM_ SG_ 2333470355 M2P_SUMDATA5_CUS_Reserved5_03 "MBMU客户预留信号";
CM_ SG_ 2333470356 M2P_SUMDATA5_CUS_Reserved5_04 "MBMU客户预留信号";
CM_ SG_ 2333470357 M2P_SUMDATA5_CUS_Reserved5_05 "MBMU客户预留信号";
CM_ SG_ 2333470358 M2P_SUMDATA5_CUS_Reserved5_06 "MBMU客户预留信号";
CM_ SG_ 2333470359 M2P_SUMDATA5_CUS_Reserved5_07 "MBMU客户预留信号";
CM_ SG_ 2333470360 M2P_SUMDATA5_CUS_Reserved5_08 "MBMU客户预留信号";
CM_ SG_ 2333470361 M2P_SUMDATA5_CUS_Reserved5_09 "MBMU客户预留信号";
CM_ SG_ 2333470362 M2P_SUMDATA5_CUS_Reserved5_10 "MBMU客户预留信号";
CM_ SG_ 2333470363 M2P_SUMDATA5_CUS_Reserved5_11 "MBMU客户预留信号";
CM_ SG_ 2333470364 M2P_SUMDATA5_CUS_Reserved5_12 "MBMU客户预留信号";
CM_ SG_ 2333470365 M2P_SUMDATA5_CUS_Reserved5_13 "MBMU客户预留信号";
CM_ SG_ 2333470366 M2P_SUMDATA5_CUS_Reserved5_14 "MBMU客户预留信号";
CM_ SG_ 2333470367 M2P_SUMDATA5_CUS_Reserved5_15 "MBMU客户预留信号";
CM_ SG_ 2333470368 M2P_SUMDATA5_CUS_Reserved5_16 "MBMU客户预留信号";
CM_ SG_ 2333470369 M2P_SUMDATA5_CUS_Reserved5_17 "MBMU客户预留信号";
CM_ SG_ 2333470370 M2P_SUMDATA5_CUS_Reserved5_18 "MBMU客户预留信号";
CM_ SG_ 2333470371 M2P_SUMDATA5_CUS_Reserved5_19 "MBMU客户预留信号";
CM_ SG_ 2333470372 M2P_SUMDATA5_CUS_Reserved5_20 "MBMU客户预留信号";
CM_ SG_ 2333470373 M2P_SUMDATA5_CUS_Reserved5_21 "MBMU客户预留信号";
CM_ SG_ 2333470374 M2P_SUMDATA5_CUS_Reserved5_22 "MBMU客户预留信号";
CM_ SG_ 2333470375 M2P_SUMDATA5_CUS_Reserved5_23 "MBMU客户预留信号";
CM_ SG_ 2333470376 M2P_SUMDATA5_CUS_Reserved5_24 "MBMU客户预留信号";
CM_ SG_ 2333470377 M2P_SUMDATA5_CUS_Reserved5_25 "MBMU客户预留信号";
CM_ SG_ 2333470378 M2P_SUMDATA5_CUS_Reserved5_26 "MBMU客户预留信号";
CM_ SG_ 2333470379 M2P_SUMDATA5_CUS_Reserved5_27 "MBMU客户预留信号";
CM_ SG_ 2333470380 M2P_SUMDATA5_CUS_Reserved5_28 "MBMU客户预留信号";
CM_ SG_ 2333470381 M2P_SUMDATA5_CUS_Reserved5_29 "MBMU客户预留信号";
CM_ SG_ 2333470382 M2P_SUMDATA5_CUS_Reserved5_30 "MBMU客户预留信号";
CM_ SG_ 2333470383 M2P_SUMDATA5_CUS_Reserved5_31 "MBMU客户预留信号";
CM_ SG_ 2332155937 I2A_Byrack_SUMDATA1_CRC_01 "IMM发送的概要数据1的CRC";
CM_ SG_ 2332155937 I2A_Byrack_SUMDATA1_ALIV_01 "IMM发送的概要数据1的生命信号，0~15循环";
CM_ SG_ 2332155937 I2A_Byrack_VoltVld_01 "IMM采样有效标志";
CM_ SG_ 2332155937 I2A_Byrack_VoltErr_01 "IMM板电源故障标志(暂未使用）";
CM_ SG_ 2332155937 I2A_Byrack_InsResValid_01 "IMM绝缘阻值有效性";
CM_ SG_ 2332155937 Reserved_01 "预留";
CM_ SG_ 2332155937 I2A_Byrack_IsoResPos_01 "主正对机壳的有效绝缘阻值";
CM_ SG_ 2332155937 I2A_Byrack_IsoResNeg_01 "主负对机壳的有效绝缘阻值";
CM_ SG_ 2332155938 I2A_Byrack_SUMDATA1_CRC_02 "IMM发送的概要数据1的CRC";
CM_ SG_ 2332155938 I2A_Byrack_SUMDATA1_ALIV_02 "IMM发送的概要数据1的生命信号，0~15循环";
CM_ SG_ 2332155938 I2A_Byrack_VoltVld_02 "IMM采样有效标志";
CM_ SG_ 2332155938 I2A_Byrack_VoltErr_02 "IMM板电源故障标志(暂未使用）";
CM_ SG_ 2332155938 I2A_Byrack_InsResValid_02 "IMM绝缘阻值有效性";
CM_ SG_ 2332155938 Reserved_02 "预留";
CM_ SG_ 2332155938 I2A_Byrack_IsoResPos_02 "主正对机壳的有效绝缘阻值";
CM_ SG_ 2332155938 I2A_Byrack_IsoResNeg_02 "主负对机壳的有效绝缘阻值";
CM_ SG_ 2332155939 I2A_Byrack_SUMDATA1_CRC_03 "IMM发送的概要数据1的CRC";
CM_ SG_ 2332155939 I2A_Byrack_SUMDATA1_ALIV_03 "IMM发送的概要数据1的生命信号，0~15循环";
CM_ SG_ 2332155939 I2A_Byrack_VoltVld_03 "IMM采样有效标志";
CM_ SG_ 2332155939 I2A_Byrack_VoltErr_03 "IMM板电源故障标志(暂未使用）";
CM_ SG_ 2332155939 I2A_Byrack_InsResValid_03 "IMM绝缘阻值有效性";
CM_ SG_ 2332155939 Reserved_03 "预留";
CM_ SG_ 2332155939 I2A_Byrack_IsoResPos_03 "主正对机壳的有效绝缘阻值";
CM_ SG_ 2332155939 I2A_Byrack_IsoResNeg_03 "主负对机壳的有效绝缘阻值";
CM_ SG_ 2332155940 I2A_Byrack_SUMDATA1_CRC_04 "IMM发送的概要数据1的CRC";
CM_ SG_ 2332155940 I2A_Byrack_SUMDATA1_ALIV_04 "IMM发送的概要数据1的生命信号，0~15循环";
CM_ SG_ 2332155940 I2A_Byrack_VoltVld_04 "IMM采样有效标志";
CM_ SG_ 2332155940 I2A_Byrack_VoltErr_04 "IMM板电源故障标志(暂未使用）";
CM_ SG_ 2332155940 I2A_Byrack_InsResValid_04 "IMM绝缘阻值有效性";
CM_ SG_ 2332155940 Reserved_04 "预留";
CM_ SG_ 2332155940 I2A_Byrack_IsoResPos_04 "主正对机壳的有效绝缘阻值";
CM_ SG_ 2332155940 I2A_Byrack_IsoResNeg_04 "主负对机壳的有效绝缘阻值";
CM_ SG_ 2332155941 I2A_Byrack_SUMDATA1_CRC_05 "IMM发送的概要数据1的CRC";
CM_ SG_ 2332155941 I2A_Byrack_SUMDATA1_ALIV_05 "IMM发送的概要数据1的生命信号，0~15循环";
CM_ SG_ 2332155941 I2A_Byrack_VoltVld_05 "IMM采样有效标志";
CM_ SG_ 2332155941 I2A_Byrack_VoltErr_05 "IMM板电源故障标志(暂未使用）";
CM_ SG_ 2332155941 I2A_Byrack_InsResValid_05 "IMM绝缘阻值有效性";
CM_ SG_ 2332155941 Reserved_05 "预留";
CM_ SG_ 2332155941 I2A_Byrack_IsoResPos_05 "主正对机壳的有效绝缘阻值";
CM_ SG_ 2332155941 I2A_Byrack_IsoResNeg_05 "主负对机壳的有效绝缘阻值";
VAL_ 2332155937 I2A_Byrack_VoltVld_01 0 "invalid" 1 "Valid" ;
VAL_ 2332155937 I2A_Byrack_VoltErr_01 0 "normal" 1 "error" ;
VAL_ 2332155937 I2A_Byrack_InsResValid_01 0 "invalid" 1 "Valid" ;
VAL_ 2332155937 I2A_Byrack_IsoResPos_01 0 "invalid" 1 "Valid" 2 "Init" ;
VAL_ 2332155938 I2A_Byrack_VoltVld_02 0 "invalid" 1 "Valid" ;
VAL_ 2332155938 I2A_Byrack_VoltErr_02 0 "normal" 1 "error" ;
VAL_ 2332155938 I2A_Byrack_InsResValid_02 0 "invalid" 1 "Valid" ;
VAL_ 2332155938 I2A_Byrack_IsoResPos_02 0 "invalid" 1 "Valid" 2 "Init" ;
VAL_ 2332155939 I2A_Byrack_VoltVld_03 0 "invalid" 1 "Valid" ;
VAL_ 2332155939 I2A_Byrack_VoltErr_03 0 "normal" 1 "error" ;
VAL_ 2332155939 I2A_Byrack_InsResValid_03 0 "invalid" 1 "Valid" ;
VAL_ 2332155939 I2A_Byrack_IsoResPos_03 0 "invalid" 1 "Valid" 2 "Init" ;
VAL_ 2332155940 I2A_Byrack_VoltVld_04 0 "invalid" 1 "Valid" ;
VAL_ 2332155940 I2A_Byrack_VoltErr_04 0 "normal" 1 "error" ;
VAL_ 2332155940 I2A_Byrack_InsResValid_04 0 "invalid" 1 "Valid" ;
VAL_ 2332155940 I2A_Byrack_IsoResPos_04 0 "invalid" 1 "Valid" 2 "Init" ;
VAL_ 2332155941 I2A_Byrack_VoltVld_05 0 "invalid" 1 "Valid" ;
VAL_ 2332155941 I2A_Byrack_VoltErr_05 0 "normal" 1 "error" ;
VAL_ 2332155941 I2A_Byrack_InsResValid_05 0 "invalid" 1 "Valid" ;
VAL_ 2332155941 I2A_Byrack_IsoResPos_05 0 "invalid" 1 "Valid" 2 "Init" ;
VERSION ""

NS_ :

BS_:

BU_: MBMU PC SBMU IMM ETH DCDC LEMS

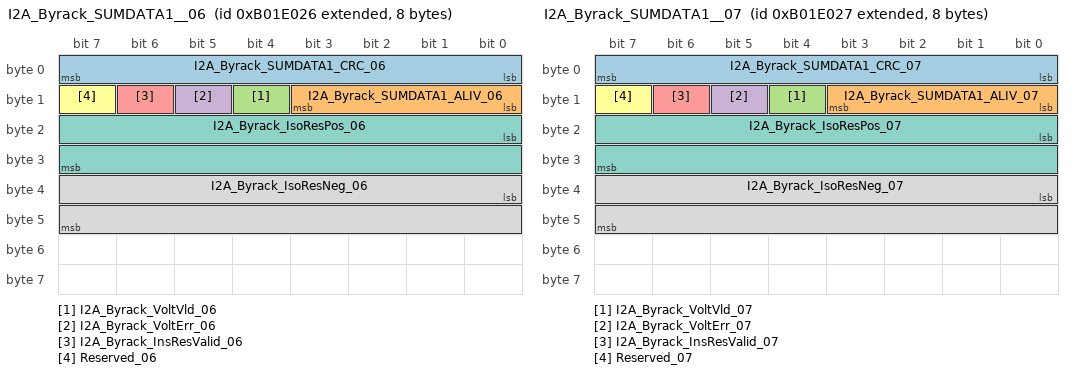
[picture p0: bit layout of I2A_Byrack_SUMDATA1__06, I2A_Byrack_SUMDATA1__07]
BO_ 2332155942 I2A_Byrack_SUMDATA1__06: 8 IMM
 SG_ I2A_Byrack_SUMDATA1_CRC_06 : 0|8@1+ (1,0) [0|255] ""  MBMU,PC
 SG_ I2A_Byrack_SUMDATA1_ALIV_06 : 8|4@1+ (1,0) [0|15] ""  MBMU,PC
 SG_ I2A_Byrack_VoltVld_06 : 12|1@1+ (1,0) [0|1] ""  MBMU,PC
 SG_ I2A_Byrack_VoltErr_06 : 13|1@1+ (1,0) [0|1] ""  MBMU,PC
 SG_ I2A_Byrack_InsResValid_06 : 14|1@1+ (1,0) [0|1] ""  MBMU,PC
 SG_ Reserved_06 : 15|1@1+ (1,0) [0|1] ""  MBMU,PC
 SG_ I2A_Byrack_IsoResPos_06 : 16|16@1+ (1,0) [0|65535] "KΩ"  MBMU,PC
 SG_ I2A_Byrack_IsoResNeg_06 : 32|16@1+ (1,0) [0|65535] "KΩ"  MBMU,PC

BO_ 2332155943 I2A_Byrack_SUMDATA1__07: 8 IMM
 SG_ I2A_Byrack_SUMDATA1_CRC_07 : 0|8@1+ (1,0) [0|255] ""  MBMU,PC
 SG_ I2A_Byrack_SUMDATA1_ALIV_07 : 8|4@1+ (1,0) [0|15] ""  MBMU,PC
 SG_ I2A_Byrack_VoltVld_07 : 12|1@1+ (1,0) [0|1] ""  MBMU,PC
 SG_ I2A_Byrack_VoltErr_07 : 13|1@1+ (1,0) [0|1] ""  MBMU,PC
 SG_ I2A_Byrack_InsResValid_07 : 14|1@1+ (1,0) [0|1] ""  MBMU,PC
 SG_ Reserved_07 : 15|1@1+ (1,0) [0|1] ""  MBMU,PC
 SG_ I2A_Byrack_IsoResPos_07 : 16|16@1+ (1,0) [0|65535] "KΩ"  MBMU,PC
 SG_ I2A_Byrack_IsoResNeg_07 : 32|16@1+ (1,0) [0|65535] "KΩ"  MBMU,PC

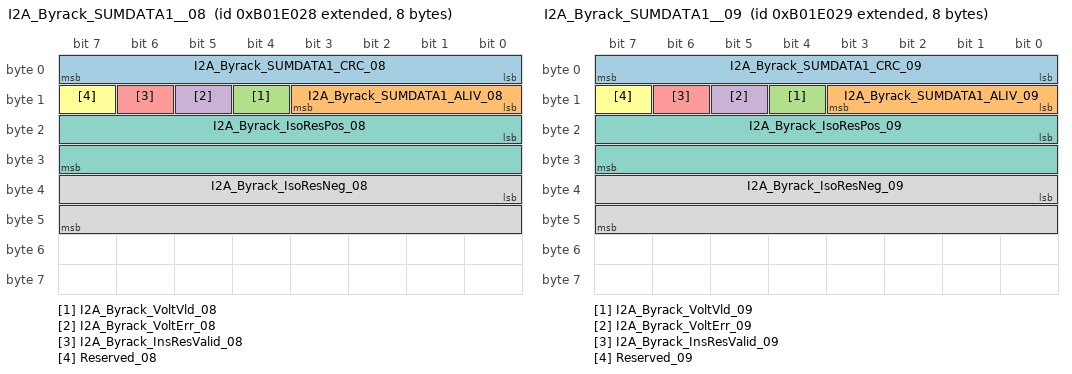
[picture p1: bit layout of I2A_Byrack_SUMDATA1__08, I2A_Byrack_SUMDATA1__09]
BO_ 2332155944 I2A_Byrack_SUMDATA1__08: 8 IMM
 SG_ I2A_Byrack_SUMDATA1_CRC_08 : 0|8@1+ (1,0) [0|255] ""  MBMU,PC
 SG_ I2A_Byrack_SUMDATA1_ALIV_08 : 8|4@1+ (1,0) [0|15] ""  MBMU,PC
 SG_ I2A_Byrack_VoltVld_08 : 12|1@1+ (1,0) [0|1] ""  MBMU,PC
 SG_ I2A_Byrack_VoltErr_08 : 13|1@1+ (1,0) [0|1] ""  MBMU,PC
 SG_ I2A_Byrack_InsResValid_08 : 14|1@1+ (1,0) [0|1] ""  MBMU,PC
 SG_ Reserved_08 : 15|1@1+ (1,0) [0|1] ""  MBMU,PC
 SG_ I2A_Byrack_IsoResPos_08 : 16|16@1+ (1,0) [0|65535] "KΩ"  MBMU,PC
 SG_ I2A_Byrack_IsoResNeg_08 : 32|16@1+ (1,0) [0|65535] "KΩ"  MBMU,PC

BO_ 2332155945 I2A_Byrack_SUMDATA1__09: 8 IMM
 SG_ I2A_Byrack_SUMDATA1_CRC_09 : 0|8@1+ (1,0) [0|255] ""  MBMU,PC
 SG_ I2A_Byrack_SUMDATA1_ALIV_09 : 8|4@1+ (1,0) [0|15] ""  MBMU,PC
 SG_ I2A_Byrack_VoltVld_09 : 12|1@1+ (1,0) [0|1] ""  MBMU,PC
 SG_ I2A_Byrack_VoltErr_09 : 13|1@1+ (1,0) [0|1] ""  MBMU,PC
 SG_ I2A_Byrack_InsResValid_09 : 14|1@1+ (1,0) [0|1] ""  MBMU,PC
 SG_ Reserved_09 : 15|1@1+ (1,0) [0|1] ""  MBMU,PC
 SG_ I2A_Byrack_IsoResPos_09 : 16|16@1+ (1,0) [0|65535] "KΩ"  MBMU,PC
 SG_ I2A_Byrack_IsoResNeg_09 : 32|16@1+ (1,0) [0|65535] "KΩ"  MBMU,PC

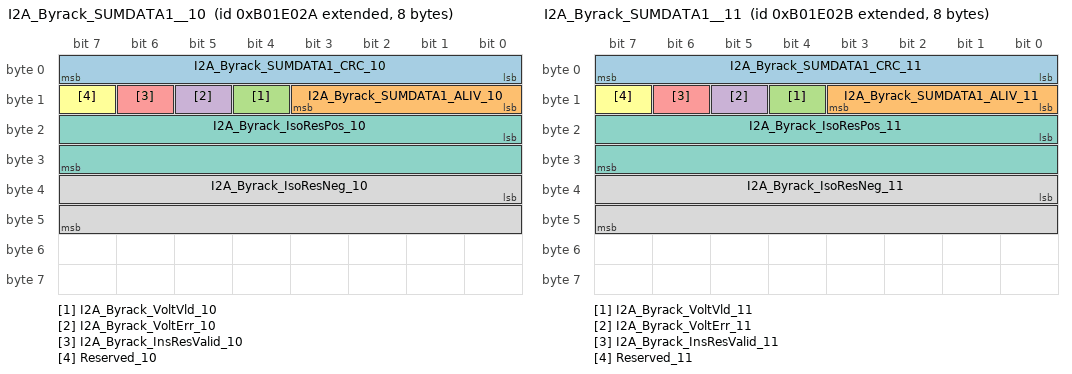
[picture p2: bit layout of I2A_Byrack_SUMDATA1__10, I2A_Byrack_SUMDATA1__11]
BO_ 2332155946 I2A_Byrack_SUMDATA1__10: 8 IMM
 SG_ I2A_Byrack_SUMDATA1_CRC_10 : 0|8@1+ (1,0) [0|255] ""  MBMU,PC
 SG_ I2A_Byrack_SUMDATA1_ALIV_10 : 8|4@1+ (1,0) [0|15] ""  MBMU,PC
 SG_ I2A_Byrack_VoltVld_10 : 12|1@1+ (1,0) [0|1] ""  MBMU,PC
 SG_ I2A_Byrack_VoltErr_10 : 13|1@1+ (1,0) [0|1] ""  MBMU,PC
 SG_ I2A_Byrack_InsResValid_10 : 14|1@1+ (1,0) [0|1] ""  MBMU,PC
 SG_ Reserved_10 : 15|1@1+ (1,0) [0|1] ""  MBMU,PC
 SG_ I2A_Byrack_IsoResPos_10 : 16|16@1+ (1,0) [0|65535] "KΩ"  MBMU,PC
 SG_ I2A_Byrack_IsoResNeg_10 : 32|16@1+ (1,0) [0|65535] "KΩ"  MBMU,PC

BO_ 2332155947 I2A_Byrack_SUMDATA1__11: 8 IMM
 SG_ I2A_Byrack_SUMDATA1_CRC_11 : 0|8@1+ (1,0) [0|255] ""  MBMU,PC
 SG_ I2A_Byrack_SUMDATA1_ALIV_11 : 8|4@1+ (1,0) [0|15] ""  MBMU,PC
 SG_ I2A_Byrack_VoltVld_11 : 12|1@1+ (1,0) [0|1] ""  MBMU,PC
 SG_ I2A_Byrack_VoltErr_11 : 13|1@1+ (1,0) [0|1] ""  MBMU,PC
 SG_ I2A_Byrack_InsResValid_11 : 14|1@1+ (1,0) [0|1] ""  MBMU,PC
 SG_ Reserved_11 : 15|1@1+ (1,0) [0|1] ""  MBMU,PC
 SG_ I2A_Byrack_IsoResPos_11 : 16|16@1+ (1,0) [0|65535] "KΩ"  MBMU,PC
 SG_ I2A_Byrack_IsoResNeg_11 : 32|16@1+ (1,0) [0|65535] "KΩ"  MBMU,PC

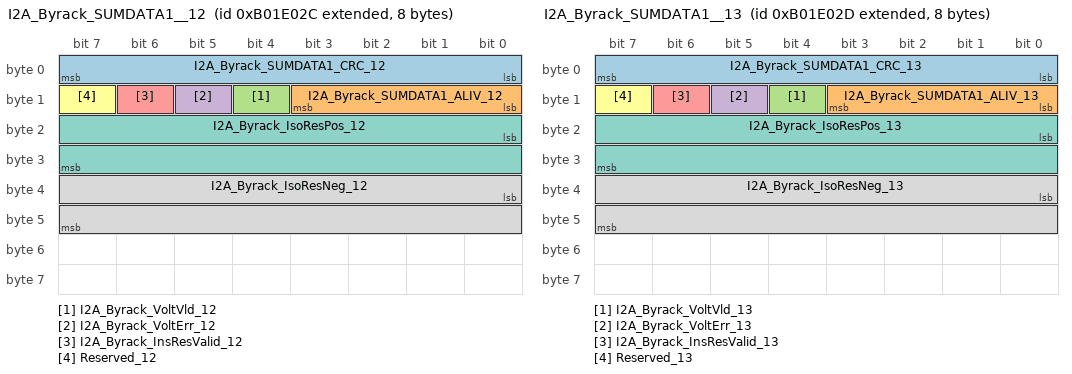
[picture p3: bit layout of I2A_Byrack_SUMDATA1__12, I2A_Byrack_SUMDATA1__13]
BO_ 2332155948 I2A_Byrack_SUMDATA1__12: 8 IMM
 SG_ I2A_Byrack_SUMDATA1_CRC_12 : 0|8@1+ (1,0) [0|255] ""  MBMU,PC
 SG_ I2A_Byrack_SUMDATA1_ALIV_12 : 8|4@1+ (1,0) [0|15] ""  MBMU,PC
 SG_ I2A_Byrack_VoltVld_12 : 12|1@1+ (1,0) [0|1] ""  MBMU,PC
 SG_ I2A_Byrack_VoltErr_12 : 13|1@1+ (1,0) [0|1] ""  MBMU,PC
 SG_ I2A_Byrack_InsResValid_12 : 14|1@1+ (1,0) [0|1] ""  MBMU,PC
 SG_ Reserved_12 : 15|1@1+ (1,0) [0|1] ""  MBMU,PC
 SG_ I2A_Byrack_IsoResPos_12 : 16|16@1+ (1,0) [0|65535] "KΩ"  MBMU,PC
 SG_ I2A_Byrack_IsoResNeg_12 : 32|16@1+ (1,0) [0|65535] "KΩ"  MBMU,PC

BO_ 2332155949 I2A_Byrack_SUMDATA1__13: 8 IMM
 SG_ I2A_Byrack_SUMDATA1_CRC_13 : 0|8@1+ (1,0) [0|255] ""  MBMU,PC
 SG_ I2A_Byrack_SUMDATA1_ALIV_13 : 8|4@1+ (1,0) [0|15] ""  MBMU,PC
 SG_ I2A_Byrack_VoltVld_13 : 12|1@1+ (1,0) [0|1] ""  MBMU,PC
 SG_ I2A_Byrack_VoltErr_13 : 13|1@1+ (1,0) [0|1] ""  MBMU,PC
 SG_ I2A_Byrack_InsResValid_13 : 14|1@1+ (1,0) [0|1] ""  MBMU,PC
 SG_ Reserved_13 : 15|1@1+ (1,0) [0|1] ""  MBMU,PC
 SG_ I2A_Byrack_IsoResPos_13 : 16|16@1+ (1,0) [0|65535] "KΩ"  MBMU,PC
 SG_ I2A_Byrack_IsoResNeg_13 : 32|16@1+ (1,0) [0|65535] "KΩ"  MBMU,PC

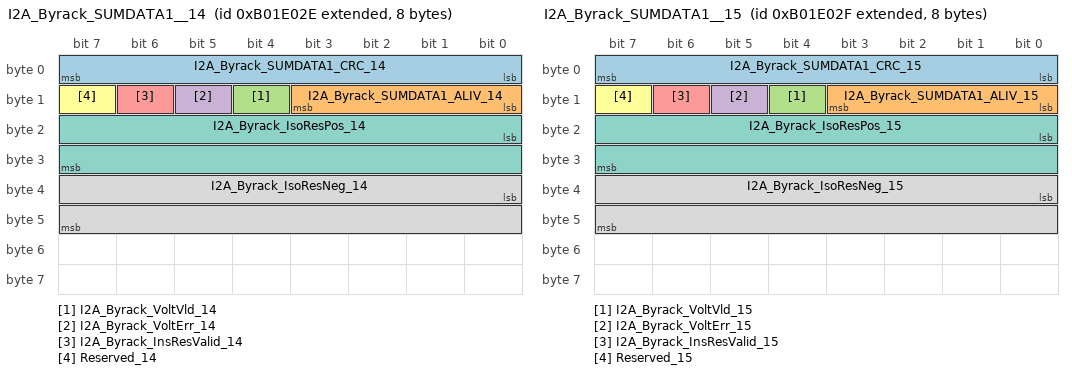
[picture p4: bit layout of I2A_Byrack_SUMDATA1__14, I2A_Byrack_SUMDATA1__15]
BO_ 2332155950 I2A_Byrack_SUMDATA1__14: 8 IMM
 SG_ I2A_Byrack_SUMDATA1_CRC_14 : 0|8@1+ (1,0) [0|255] ""  MBMU,PC
 SG_ I2A_Byrack_SUMDATA1_ALIV_14 : 8|4@1+ (1,0) [0|15] ""  MBMU,PC
 SG_ I2A_Byrack_VoltVld_14 : 12|1@1+ (1,0) [0|1] ""  MBMU,PC
 SG_ I2A_Byrack_VoltErr_14 : 13|1@1+ (1,0) [0|1] ""  MBMU,PC
 SG_ I2A_Byrack_InsResValid_14 : 14|1@1+ (1,0) [0|1] ""  MBMU,PC
 SG_ Reserved_14 : 15|1@1+ (1,0) [0|1] ""  MBMU,PC
 SG_ I2A_Byrack_IsoResPos_14 : 16|16@1+ (1,0) [0|65535] "KΩ"  MBMU,PC
 SG_ I2A_Byrack_IsoResNeg_14 : 32|16@1+ (1,0) [0|65535] "KΩ"  MBMU,PC

BO_ 2332155951 I2A_Byrack_SUMDATA1__15: 8 IMM
 SG_ I2A_Byrack_SUMDATA1_CRC_15 : 0|8@1+ (1,0) [0|255] ""  MBMU,PC
 SG_ I2A_Byrack_SUMDATA1_ALIV_15 : 8|4@1+ (1,0) [0|15] ""  MBMU,PC
 SG_ I2A_Byrack_VoltVld_15 : 12|1@1+ (1,0) [0|1] ""  MBMU,PC
 SG_ I2A_Byrack_VoltErr_15 : 13|1@1+ (1,0) [0|1] ""  MBMU,PC
 SG_ I2A_Byrack_InsResValid_15 : 14|1@1+ (1,0) [0|1] ""  MBMU,PC
 SG_ Reserved_15 : 15|1@1+ (1,0) [0|1] ""  MBMU,PC
 SG_ I2A_Byrack_IsoResPos_15 : 16|16@1+ (1,0) [0|65535] "KΩ"  MBMU,PC
 SG_ I2A_Byrack_IsoResNeg_15 : 32|16@1+ (1,0) [0|65535] "KΩ"  MBMU,PC

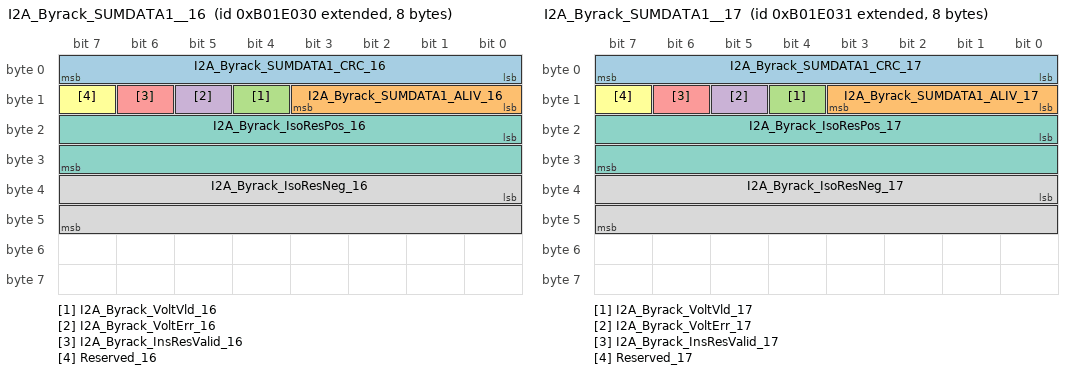
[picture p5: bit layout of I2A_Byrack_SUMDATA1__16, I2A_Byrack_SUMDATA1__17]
BO_ 2332155952 I2A_Byrack_SUMDATA1__16: 8 IMM
 SG_ I2A_Byrack_SUMDATA1_CRC_16 : 0|8@1+ (1,0) [0|255] ""  MBMU,PC
 SG_ I2A_Byrack_SUMDATA1_ALIV_16 : 8|4@1+ (1,0) [0|15] ""  MBMU,PC
 SG_ I2A_Byrack_VoltVld_16 : 12|1@1+ (1,0) [0|1] ""  MBMU,PC
 SG_ I2A_Byrack_VoltErr_16 : 13|1@1+ (1,0) [0|1] ""  MBMU,PC
 SG_ I2A_Byrack_InsResValid_16 : 14|1@1+ (1,0) [0|1] ""  MBMU,PC
 SG_ Reserved_16 : 15|1@1+ (1,0) [0|1] ""  MBMU,PC
 SG_ I2A_Byrack_IsoResPos_16 : 16|16@1+ (1,0) [0|65535] "KΩ"  MBMU,PC
 SG_ I2A_Byrack_IsoResNeg_16 : 32|16@1+ (1,0) [0|65535] "KΩ"  MBMU,PC

BO_ 2332155953 I2A_Byrack_SUMDATA1__17: 8 IMM
 SG_ I2A_Byrack_SUMDATA1_CRC_17 : 0|8@1+ (1,0) [0|255] ""  MBMU,PC
 SG_ I2A_Byrack_SUMDATA1_ALIV_17 : 8|4@1+ (1,0) [0|15] ""  MBMU,PC
 SG_ I2A_Byrack_VoltVld_17 : 12|1@1+ (1,0) [0|1] ""  MBMU,PC
 SG_ I2A_Byrack_VoltErr_17 : 13|1@1+ (1,0) [0|1] ""  MBMU,PC
 SG_ I2A_Byrack_InsResValid_17 : 14|1@1+ (1,0) [0|1] ""  MBMU,PC
 SG_ Reserved_17 : 15|1@1+ (1,0) [0|1] ""  MBMU,PC
 SG_ I2A_Byrack_IsoResPos_17 : 16|16@1+ (1,0) [0|65535] "KΩ"  MBMU,PC
 SG_ I2A_Byrack_IsoResNeg_17 : 32|16@1+ (1,0) [0|65535] "KΩ"  MBMU,PC

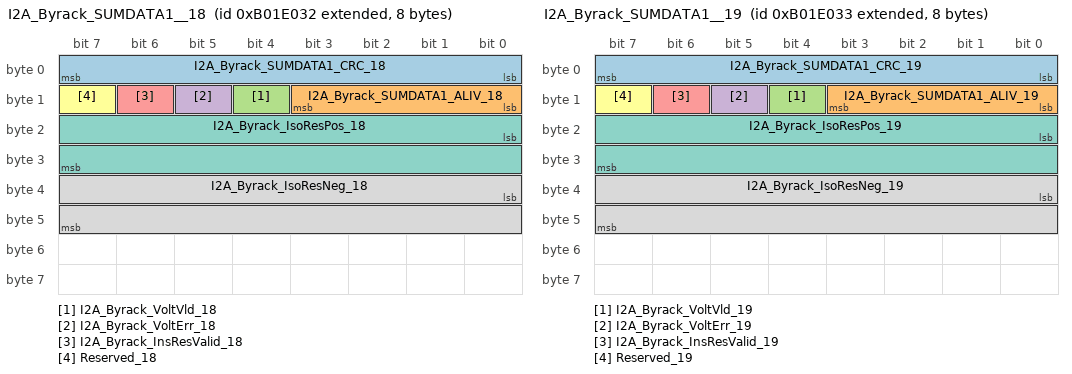
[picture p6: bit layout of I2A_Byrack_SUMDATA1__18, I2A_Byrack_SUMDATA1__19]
BO_ 2332155954 I2A_Byrack_SUMDATA1__18: 8 IMM
 SG_ I2A_Byrack_SUMDATA1_CRC_18 : 0|8@1+ (1,0) [0|255] ""  MBMU,PC
 SG_ I2A_Byrack_SUMDATA1_ALIV_18 : 8|4@1+ (1,0) [0|15] ""  MBMU,PC
 SG_ I2A_Byrack_VoltVld_18 : 12|1@1+ (1,0) [0|1] ""  MBMU,PC
 SG_ I2A_Byrack_VoltErr_18 : 13|1@1+ (1,0) [0|1] ""  MBMU,PC
 SG_ I2A_Byrack_InsResValid_18 : 14|1@1+ (1,0) [0|1] ""  MBMU,PC
 SG_ Reserved_18 : 15|1@1+ (1,0) [0|1] ""  MBMU,PC
 SG_ I2A_Byrack_IsoResPos_18 : 16|16@1+ (1,0) [0|65535] "KΩ"  MBMU,PC
 SG_ I2A_Byrack_IsoResNeg_18 : 32|16@1+ (1,0) [0|65535] "KΩ"  MBMU,PC

BO_ 2332155955 I2A_Byrack_SUMDATA1__19: 8 IMM
 SG_ I2A_Byrack_SUMDATA1_CRC_19 : 0|8@1+ (1,0) [0|255] ""  MBMU,PC
 SG_ I2A_Byrack_SUMDATA1_ALIV_19 : 8|4@1+ (1,0) [0|15] ""  MBMU,PC
 SG_ I2A_Byrack_VoltVld_19 : 12|1@1+ (1,0) [0|1] ""  MBMU,PC
 SG_ I2A_Byrack_VoltErr_19 : 13|1@1+ (1,0) [0|1] ""  MBMU,PC
 SG_ I2A_Byrack_InsResValid_19 : 14|1@1+ (1,0) [0|1] ""  MBMU,PC
 SG_ Reserved_19 : 15|1@1+ (1,0) [0|1] ""  MBMU,PC
 SG_ I2A_Byrack_IsoResPos_19 : 16|16@1+ (1,0) [0|65535] "KΩ"  MBMU,PC
 SG_ I2A_Byrack_IsoResNeg_19 : 32|16@1+ (1,0) [0|65535] "KΩ"  MBMU,PC

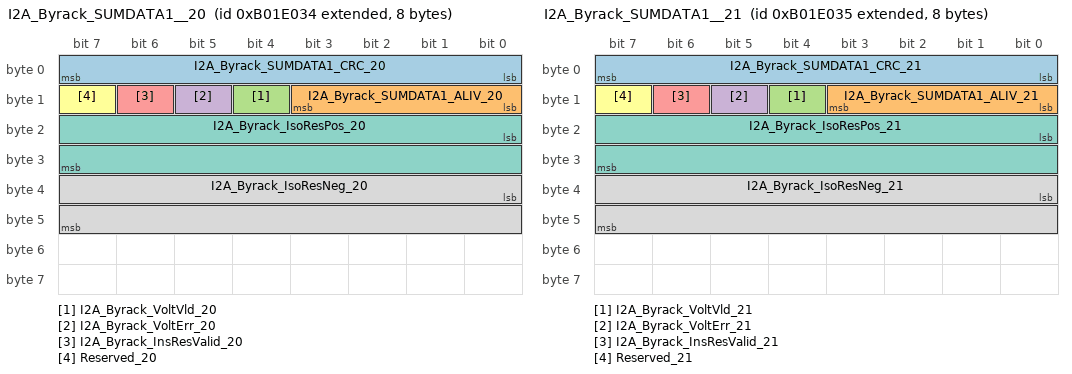
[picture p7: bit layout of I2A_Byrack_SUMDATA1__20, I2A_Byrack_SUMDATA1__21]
BO_ 2332155956 I2A_Byrack_SUMDATA1__20: 8 IMM
 SG_ I2A_Byrack_SUMDATA1_CRC_20 : 0|8@1+ (1,0) [0|255] ""  MBMU,PC
 SG_ I2A_Byrack_SUMDATA1_ALIV_20 : 8|4@1+ (1,0) [0|15] ""  MBMU,PC
 SG_ I2A_Byrack_VoltVld_20 : 12|1@1+ (1,0) [0|1] ""  MBMU,PC
 SG_ I2A_Byrack_VoltErr_20 : 13|1@1+ (1,0) [0|1] ""  MBMU,PC
 SG_ I2A_Byrack_InsResValid_20 : 14|1@1+ (1,0) [0|1] ""  MBMU,PC
 SG_ Reserved_20 : 15|1@1+ (1,0) [0|1] ""  MBMU,PC
 SG_ I2A_Byrack_IsoResPos_20 : 16|16@1+ (1,0) [0|65535] "KΩ"  MBMU,PC
 SG_ I2A_Byrack_IsoResNeg_20 : 32|16@1+ (1,0) [0|65535] "KΩ"  MBMU,PC

BO_ 2332155957 I2A_Byrack_SUMDATA1__21: 8 IMM
 SG_ I2A_Byrack_SUMDATA1_CRC_21 : 0|8@1+ (1,0) [0|255] ""  MBMU,PC
 SG_ I2A_Byrack_SUMDATA1_ALIV_21 : 8|4@1+ (1,0) [0|15] ""  MBMU,PC
 SG_ I2A_Byrack_VoltVld_21 : 12|1@1+ (1,0) [0|1] ""  MBMU,PC
 SG_ I2A_Byrack_VoltErr_21 : 13|1@1+ (1,0) [0|1] ""  MBMU,PC
 SG_ I2A_Byrack_InsResValid_21 : 14|1@1+ (1,0) [0|1] ""  MBMU,PC
 SG_ Reserved_21 : 15|1@1+ (1,0) [0|1] ""  MBMU,PC
 SG_ I2A_Byrack_IsoResPos_21 : 16|16@1+ (1,0) [0|65535] "KΩ"  MBMU,PC
 SG_ I2A_Byrack_IsoResNeg_21 : 32|16@1+ (1,0) [0|65535] "KΩ"  MBMU,PC

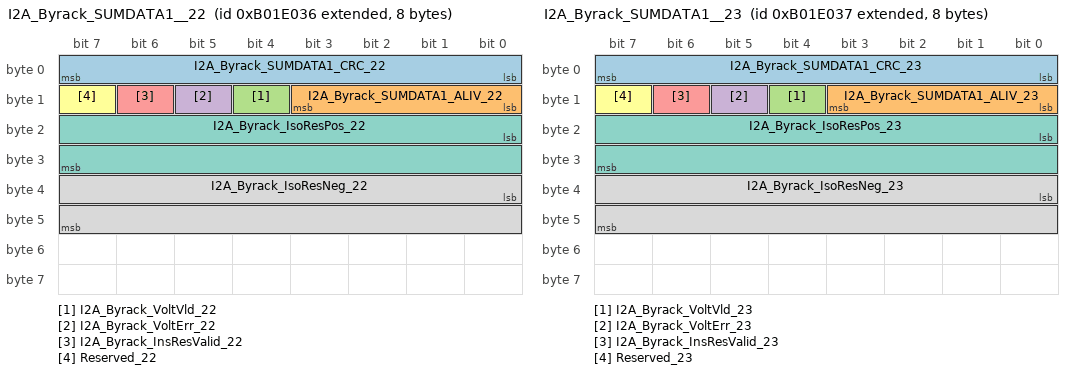
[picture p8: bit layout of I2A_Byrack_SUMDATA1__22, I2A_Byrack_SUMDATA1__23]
BO_ 2332155958 I2A_Byrack_SUMDATA1__22: 8 IMM
 SG_ I2A_Byrack_SUMDATA1_CRC_22 : 0|8@1+ (1,0) [0|255] ""  MBMU,PC
 SG_ I2A_Byrack_SUMDATA1_ALIV_22 : 8|4@1+ (1,0) [0|15] ""  MBMU,PC
 SG_ I2A_Byrack_VoltVld_22 : 12|1@1+ (1,0) [0|1] ""  MBMU,PC
 SG_ I2A_Byrack_VoltErr_22 : 13|1@1+ (1,0) [0|1] ""  MBMU,PC
 SG_ I2A_Byrack_InsResValid_22 : 14|1@1+ (1,0) [0|1] ""  MBMU,PC
 SG_ Reserved_22 : 15|1@1+ (1,0) [0|1] ""  MBMU,PC
 SG_ I2A_Byrack_IsoResPos_22 : 16|16@1+ (1,0) [0|65535] "KΩ"  MBMU,PC
 SG_ I2A_Byrack_IsoResNeg_22 : 32|16@1+ (1,0) [0|65535] "KΩ"  MBMU,PC

BO_ 2332155959 I2A_Byrack_SUMDATA1__23: 8 IMM
 SG_ I2A_Byrack_SUMDATA1_CRC_23 : 0|8@1+ (1,0) [0|255] ""  MBMU,PC
 SG_ I2A_Byrack_SUMDATA1_ALIV_23 : 8|4@1+ (1,0) [0|15] ""  MBMU,PC
 SG_ I2A_Byrack_VoltVld_23 : 12|1@1+ (1,0) [0|1] ""  MBMU,PC
 SG_ I2A_Byrack_VoltErr_23 : 13|1@1+ (1,0) [0|1] ""  MBMU,PC
 SG_ I2A_Byrack_InsResValid_23 : 14|1@1+ (1,0) [0|1] ""  MBMU,PC
 SG_ Reserved_23 : 15|1@1+ (1,0) [0|1] ""  MBMU,PC
 SG_ I2A_Byrack_IsoResPos_23 : 16|16@1+ (1,0) [0|65535] "KΩ"  MBMU,PC
 SG_ I2A_Byrack_IsoResNeg_23 : 32|16@1+ (1,0) [0|65535] "KΩ"  MBMU,PC

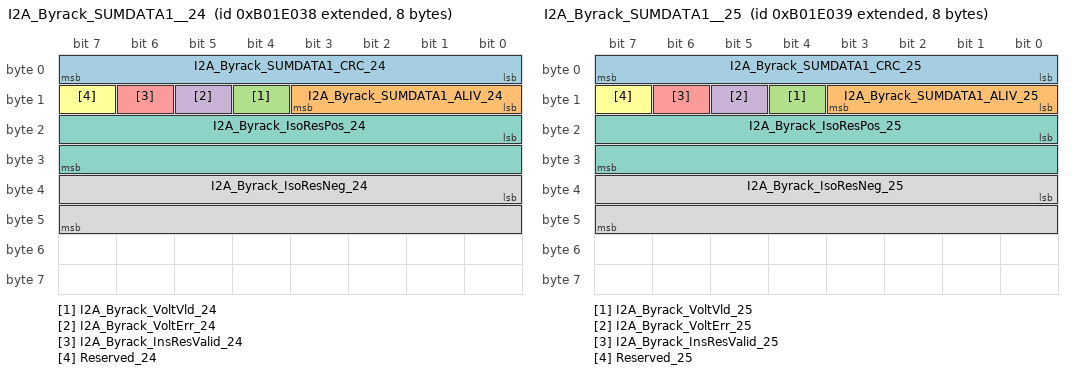
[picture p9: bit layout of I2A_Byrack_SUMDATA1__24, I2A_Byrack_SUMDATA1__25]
BO_ 2332155960 I2A_Byrack_SUMDATA1__24: 8 IMM
 SG_ I2A_Byrack_SUMDATA1_CRC_24 : 0|8@1+ (1,0) [0|255] ""  MBMU,PC
 SG_ I2A_Byrack_SUMDATA1_ALIV_24 : 8|4@1+ (1,0) [0|15] ""  MBMU,PC
 SG_ I2A_Byrack_VoltVld_24 : 12|1@1+ (1,0) [0|1] ""  MBMU,PC
 SG_ I2A_Byrack_VoltErr_24 : 13|1@1+ (1,0) [0|1] ""  MBMU,PC
 SG_ I2A_Byrack_InsResValid_24 : 14|1@1+ (1,0) [0|1] ""  MBMU,PC
 SG_ Reserved_24 : 15|1@1+ (1,0) [0|1] ""  MBMU,PC
 SG_ I2A_Byrack_IsoResPos_24 : 16|16@1+ (1,0) [0|65535] "KΩ"  MBMU,PC
 SG_ I2A_Byrack_IsoResNeg_24 : 32|16@1+ (1,0) [0|65535] "KΩ"  MBMU,PC

BO_ 2332155961 I2A_Byrack_SUMDATA1__25: 8 IMM
 SG_ I2A_Byrack_SUMDATA1_CRC_25 : 0|8@1+ (1,0) [0|255] ""  MBMU,PC
 SG_ I2A_Byrack_SUMDATA1_ALIV_25 : 8|4@1+ (1,0) [0|15] ""  MBMU,PC
 SG_ I2A_Byrack_VoltVld_25 : 12|1@1+ (1,0) [0|1] ""  MBMU,PC
 SG_ I2A_Byrack_VoltErr_25 : 13|1@1+ (1,0) [0|1] ""  MBMU,PC
 SG_ I2A_Byrack_InsResValid_25 : 14|1@1+ (1,0) [0|1] ""  MBMU,PC
 SG_ Reserved_25 : 15|1@1+ (1,0) [0|1] ""  MBMU,PC
 SG_ I2A_Byrack_IsoResPos_25 : 16|16@1+ (1,0) [0|65535] "KΩ"  MBMU,PC
 SG_ I2A_Byrack_IsoResNeg_25 : 32|16@1+ (1,0) [0|65535] "KΩ"  MBMU,PC

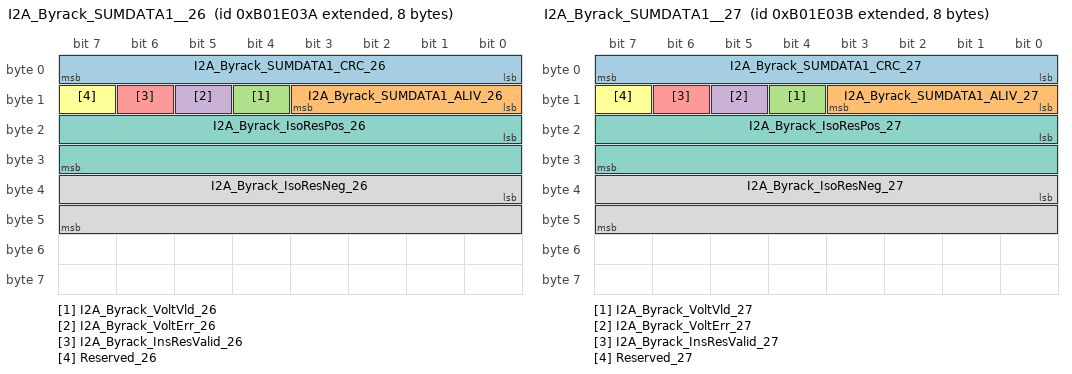
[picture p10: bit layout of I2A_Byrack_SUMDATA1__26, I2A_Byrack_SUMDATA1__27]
BO_ 2332155962 I2A_Byrack_SUMDATA1__26: 8 IMM
 SG_ I2A_Byrack_SUMDATA1_CRC_26 : 0|8@1+ (1,0) [0|255] ""  MBMU,PC
 SG_ I2A_Byrack_SUMDATA1_ALIV_26 : 8|4@1+ (1,0) [0|15] ""  MBMU,PC
 SG_ I2A_Byrack_VoltVld_26 : 12|1@1+ (1,0) [0|1] ""  MBMU,PC
 SG_ I2A_Byrack_VoltErr_26 : 13|1@1+ (1,0) [0|1] ""  MBMU,PC
 SG_ I2A_Byrack_InsResValid_26 : 14|1@1+ (1,0) [0|1] ""  MBMU,PC
 SG_ Reserved_26 : 15|1@1+ (1,0) [0|1] ""  MBMU,PC
 SG_ I2A_Byrack_IsoResPos_26 : 16|16@1+ (1,0) [0|65535] "KΩ"  MBMU,PC
 SG_ I2A_Byrack_IsoResNeg_26 : 32|16@1+ (1,0) [0|65535] "KΩ"  MBMU,PC

BO_ 2332155963 I2A_Byrack_SUMDATA1__27: 8 IMM
 SG_ I2A_Byrack_SUMDATA1_CRC_27 : 0|8@1+ (1,0) [0|255] ""  MBMU,PC
 SG_ I2A_Byrack_SUMDATA1_ALIV_27 : 8|4@1+ (1,0) [0|15] ""  MBMU,PC
 SG_ I2A_Byrack_VoltVld_27 : 12|1@1+ (1,0) [0|1] ""  MBMU,PC
 SG_ I2A_Byrack_VoltErr_27 : 13|1@1+ (1,0) [0|1] ""  MBMU,PC
 SG_ I2A_Byrack_InsResValid_27 : 14|1@1+ (1,0) [0|1] ""  MBMU,PC
 SG_ Reserved_27 : 15|1@1+ (1,0) [0|1] ""  MBMU,PC
 SG_ I2A_Byrack_IsoResPos_27 : 16|16@1+ (1,0) [0|65535] "KΩ"  MBMU,PC
 SG_ I2A_Byrack_IsoResNeg_27 : 32|16@1+ (1,0) [0|65535] "KΩ"  MBMU,PC

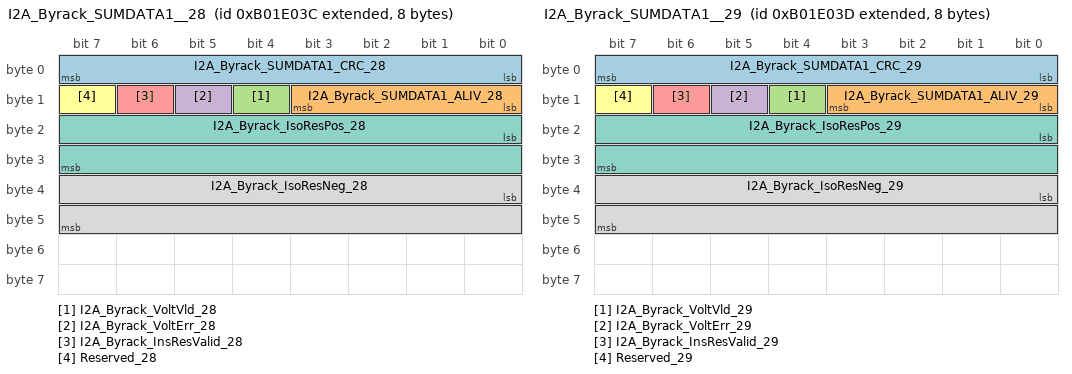
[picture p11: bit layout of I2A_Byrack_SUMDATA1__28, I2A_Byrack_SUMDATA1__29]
BO_ 2332155964 I2A_Byrack_SUMDATA1__28: 8 IMM
 SG_ I2A_Byrack_SUMDATA1_CRC_28 : 0|8@1+ (1,0) [0|255] ""  MBMU,PC
 SG_ I2A_Byrack_SUMDATA1_ALIV_28 : 8|4@1+ (1,0) [0|15] ""  MBMU,PC
 SG_ I2A_Byrack_VoltVld_28 : 12|1@1+ (1,0) [0|1] ""  MBMU,PC
 SG_ I2A_Byrack_VoltErr_28 : 13|1@1+ (1,0) [0|1] ""  MBMU,PC
 SG_ I2A_Byrack_InsResValid_28 : 14|1@1+ (1,0) [0|1] ""  MBMU,PC
 SG_ Reserved_28 : 15|1@1+ (1,0) [0|1] ""  MBMU,PC
 SG_ I2A_Byrack_IsoResPos_28 : 16|16@1+ (1,0) [0|65535] "KΩ"  MBMU,PC
 SG_ I2A_Byrack_IsoResNeg_28 : 32|16@1+ (1,0) [0|65535] "KΩ"  MBMU,PC

BO_ 2332155965 I2A_Byrack_SUMDATA1__29: 8 IMM
 SG_ I2A_Byrack_SUMDATA1_CRC_29 : 0|8@1+ (1,0) [0|255] ""  MBMU,PC
 SG_ I2A_Byrack_SUMDATA1_ALIV_29 : 8|4@1+ (1,0) [0|15] ""  MBMU,PC
 SG_ I2A_Byrack_VoltVld_29 : 12|1@1+ (1,0) [0|1] ""  MBMU,PC
 SG_ I2A_Byrack_VoltErr_29 : 13|1@1+ (1,0) [0|1] ""  MBMU,PC
 SG_ I2A_Byrack_InsResValid_29 : 14|1@1+ (1,0) [0|1] ""  MBMU,PC
 SG_ Reserved_29 : 15|1@1+ (1,0) [0|1] ""  MBMU,PC
 SG_ I2A_Byrack_IsoResPos_29 : 16|16@1+ (1,0) [0|65535] "KΩ"  MBMU,PC
 SG_ I2A_Byrack_IsoResNeg_29 : 32|16@1+ (1,0) [0|65535] "KΩ"  MBMU,PC

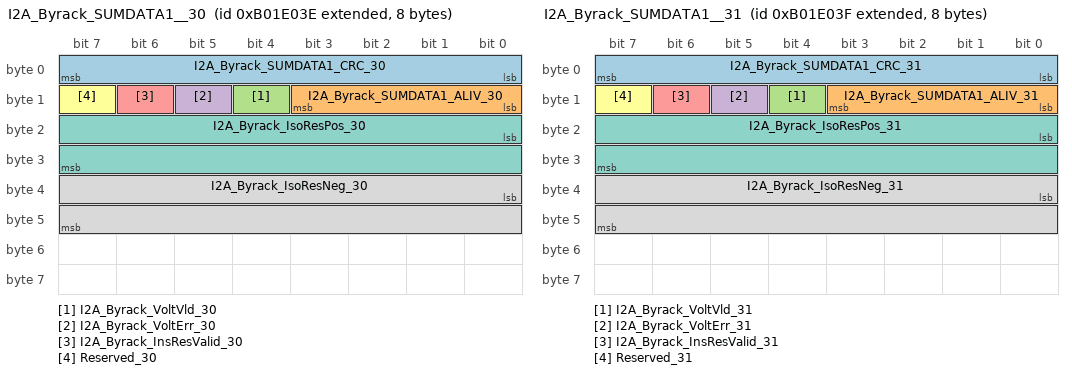
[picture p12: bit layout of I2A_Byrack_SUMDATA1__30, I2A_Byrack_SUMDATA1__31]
BO_ 2332155966 I2A_Byrack_SUMDATA1__30: 8 IMM
 SG_ I2A_Byrack_SUMDATA1_CRC_30 : 0|8@1+ (1,0) [0|255] ""  MBMU,PC
 SG_ I2A_Byrack_SUMDATA1_ALIV_30 : 8|4@1+ (1,0) [0|15] ""  MBMU,PC
 SG_ I2A_Byrack_VoltVld_30 : 12|1@1+ (1,0) [0|1] ""  MBMU,PC
 SG_ I2A_Byrack_VoltErr_30 : 13|1@1+ (1,0) [0|1] ""  MBMU,PC
 SG_ I2A_Byrack_InsResValid_30 : 14|1@1+ (1,0) [0|1] ""  MBMU,PC
 SG_ Reserved_30 : 15|1@1+ (1,0) [0|1] ""  MBMU,PC
 SG_ I2A_Byrack_IsoResPos_30 : 16|16@1+ (1,0) [0|65535] "KΩ"  MBMU,PC
 SG_ I2A_Byrack_IsoResNeg_30 : 32|16@1+ (1,0) [0|65535] "KΩ"  MBMU,PC

BO_ 2332155967 I2A_Byrack_SUMDATA1__31: 8 IMM
 SG_ I2A_Byrack_SUMDATA1_CRC_31 : 0|8@1+ (1,0) [0|255] ""  MBMU,PC
 SG_ I2A_Byrack_SUMDATA1_ALIV_31 : 8|4@1+ (1,0) [0|15] ""  MBMU,PC
 SG_ I2A_Byrack_VoltVld_31 : 12|1@1+ (1,0) [0|1] ""  MBMU,PC
 SG_ I2A_Byrack_VoltErr_31 : 13|1@1+ (1,0) [0|1] ""  MBMU,PC
 SG_ I2A_Byrack_InsResValid_31 : 14|1@1+ (1,0) [0|1] ""  MBMU,PC
 SG_ Reserved_31 : 15|1@1+ (1,0) [0|1] ""  MBMU,PC
 SG_ I2A_Byrack_IsoResPos_31 : 16|16@1+ (1,0) [0|65535] "KΩ"  MBMU,PC
 SG_ I2A_Byrack_IsoResNeg_31 : 32|16@1+ (1,0) [0|65535] "KΩ"  MBMU,PC

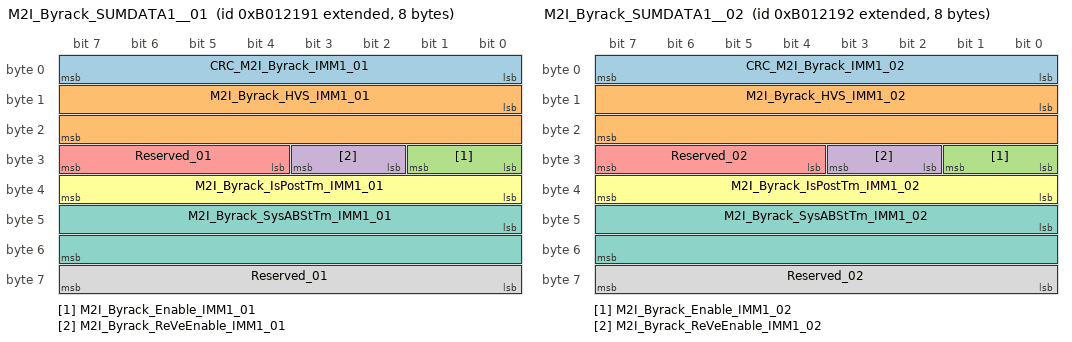
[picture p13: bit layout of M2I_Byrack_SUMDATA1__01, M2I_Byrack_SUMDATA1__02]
BO_ 2332107153 M2I_Byrack_SUMDATA1__01: 8 MBMU
 SG_ CRC_M2I_Byrack_IMM1_01 : 0|8@1+ (1,0) [0|255] ""  IMM
 SG_ M2I_Byrack_HVS_IMM1_01 : 8|16@1+ (0.1,0) [0|6553.5] "v"  IMM
 SG_ M2I_Byrack_Enable_IMM1_01 : 24|2@1+ (1,0) [0|3] ""  IMM
 SG_ M2I_Byrack_ReVeEnable_IMM1_01 : 26|2@1+ (1,0) [0|3] ""  IMM
 SG_ Reserved_01 : 28|4@1+ (1,0) [0|15] ""  IMM
 SG_ M2I_Byrack_IsPostTm_IMM1_01 : 32|8@1+ (0.01,0) [0|2.55] "s"  IMM
 SG_ M2I_Byrack_SysABStTm_IMM1_01 : 40|16@1+ (0.01,0) [0|655.35] "s"  IMM
 SG_ Reserved_01 : 56|8@1+ (1,0) [0|255] ""  IMM

BO_ 2332107154 M2I_Byrack_SUMDATA1__02: 8 MBMU
 SG_ CRC_M2I_Byrack_IMM1_02 : 0|8@1+ (1,0) [0|255] ""  IMM
 SG_ M2I_Byrack_HVS_IMM1_02 : 8|16@1+ (0.1,0) [0|6553.5] "v"  IMM
 SG_ M2I_Byrack_Enable_IMM1_02 : 24|2@1+ (1,0) [0|3] ""  IMM
 SG_ M2I_Byrack_ReVeEnable_IMM1_02 : 26|2@1+ (1,0) [0|3] ""  IMM
 SG_ Reserved_02 : 28|4@1+ (1,0) [0|15] ""  IMM
 SG_ M2I_Byrack_IsPostTm_IMM1_02 : 32|8@1+ (0.01,0) [0|2.55] "s"  IMM
 SG_ M2I_Byrack_SysABStTm_IMM1_02 : 40|16@1+ (0.01,0) [0|655.35] "s"  IMM
 SG_ Reserved_02 : 56|8@1+ (1,0) [0|255] ""  IMM

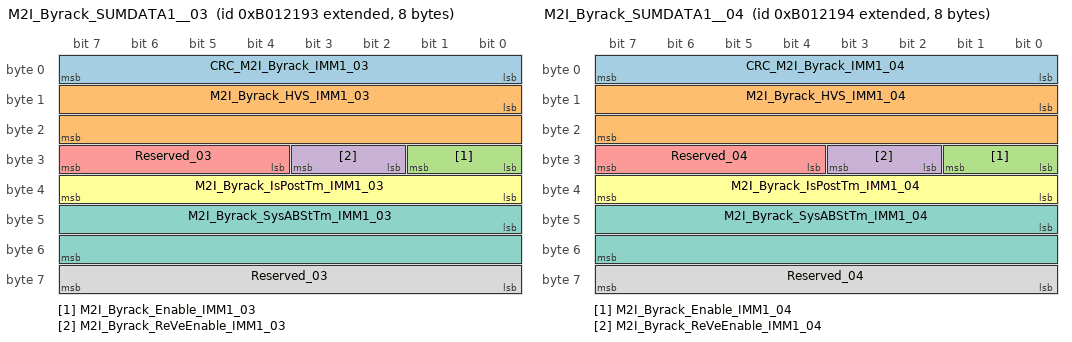
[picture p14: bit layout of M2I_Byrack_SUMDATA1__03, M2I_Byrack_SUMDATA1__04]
BO_ 2332107155 M2I_Byrack_SUMDATA1__03: 8 MBMU
 SG_ CRC_M2I_Byrack_IMM1_03 : 0|8@1+ (1,0) [0|255] ""  IMM
 SG_ M2I_Byrack_HVS_IMM1_03 : 8|16@1+ (0.1,0) [0|6553.5] "v"  IMM
 SG_ M2I_Byrack_Enable_IMM1_03 : 24|2@1+ (1,0) [0|3] ""  IMM
 SG_ M2I_Byrack_ReVeEnable_IMM1_03 : 26|2@1+ (1,0) [0|3] ""  IMM
 SG_ Reserved_03 : 28|4@1+ (1,0) [0|15] ""  IMM
 SG_ M2I_Byrack_IsPostTm_IMM1_03 : 32|8@1+ (0.01,0) [0|2.55] "s"  IMM
 SG_ M2I_Byrack_SysABStTm_IMM1_03 : 40|16@1+ (0.01,0) [0|655.35] "s"  IMM
 SG_ Reserved_03 : 56|8@1+ (1,0) [0|255] ""  IMM

BO_ 2332107156 M2I_Byrack_SUMDATA1__04: 8 MBMU
 SG_ CRC_M2I_Byrack_IMM1_04 : 0|8@1+ (1,0) [0|255] ""  IMM
 SG_ M2I_Byrack_HVS_IMM1_04 : 8|16@1+ (0.1,0) [0|6553.5] "v"  IMM
 SG_ M2I_Byrack_Enable_IMM1_04 : 24|2@1+ (1,0) [0|3] ""  IMM
 SG_ M2I_Byrack_ReVeEnable_IMM1_04 : 26|2@1+ (1,0) [0|3] ""  IMM
 SG_ Reserved_04 : 28|4@1+ (1,0) [0|15] ""  IMM
 SG_ M2I_Byrack_IsPostTm_IMM1_04 : 32|8@1+ (0.01,0) [0|2.55] "s"  IMM
 SG_ M2I_Byrack_SysABStTm_IMM1_04 : 40|16@1+ (0.01,0) [0|655.35] "s"  IMM
 SG_ Reserved_04 : 56|8@1+ (1,0) [0|255] ""  IMM

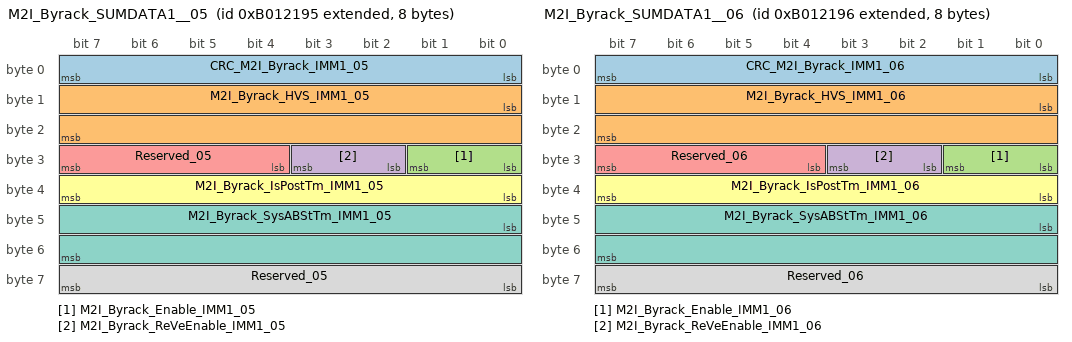
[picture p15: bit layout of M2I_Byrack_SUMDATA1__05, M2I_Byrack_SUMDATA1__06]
BO_ 2332107157 M2I_Byrack_SUMDATA1__05: 8 MBMU
 SG_ CRC_M2I_Byrack_IMM1_05 : 0|8@1+ (1,0) [0|255] ""  IMM
 SG_ M2I_Byrack_HVS_IMM1_05 : 8|16@1+ (0.1,0) [0|6553.5] "v"  IMM
 SG_ M2I_Byrack_Enable_IMM1_05 : 24|2@1+ (1,0) [0|3] ""  IMM
 SG_ M2I_Byrack_ReVeEnable_IMM1_05 : 26|2@1+ (1,0) [0|3] ""  IMM
 SG_ Reserved_05 : 28|4@1+ (1,0) [0|15] ""  IMM
 SG_ M2I_Byrack_IsPostTm_IMM1_05 : 32|8@1+ (0.01,0) [0|2.55] "s"  IMM
 SG_ M2I_Byrack_SysABStTm_IMM1_05 : 40|16@1+ (0.01,0) [0|655.35] "s"  IMM
 SG_ Reserved_05 : 56|8@1+ (1,0) [0|255] ""  IMM

BO_ 2332107158 M2I_Byrack_SUMDATA1__06: 8 MBMU
 SG_ CRC_M2I_Byrack_IMM1_06 : 0|8@1+ (1,0) [0|255] ""  IMM
 SG_ M2I_Byrack_HVS_IMM1_06 : 8|16@1+ (0.1,0) [0|6553.5] "v"  IMM
 SG_ M2I_Byrack_Enable_IMM1_06 : 24|2@1+ (1,0) [0|3] ""  IMM
 SG_ M2I_Byrack_ReVeEnable_IMM1_06 : 26|2@1+ (1,0) [0|3] ""  IMM
 SG_ Reserved_06 : 28|4@1+ (1,0) [0|15] ""  IMM
 SG_ M2I_Byrack_IsPostTm_IMM1_06 : 32|8@1+ (0.01,0) [0|2.55] "s"  IMM
 SG_ M2I_Byrack_SysABStTm_IMM1_06 : 40|16@1+ (0.01,0) [0|655.35] "s"  IMM
 SG_ Reserved_06 : 56|8@1+ (1,0) [0|255] ""  IMM

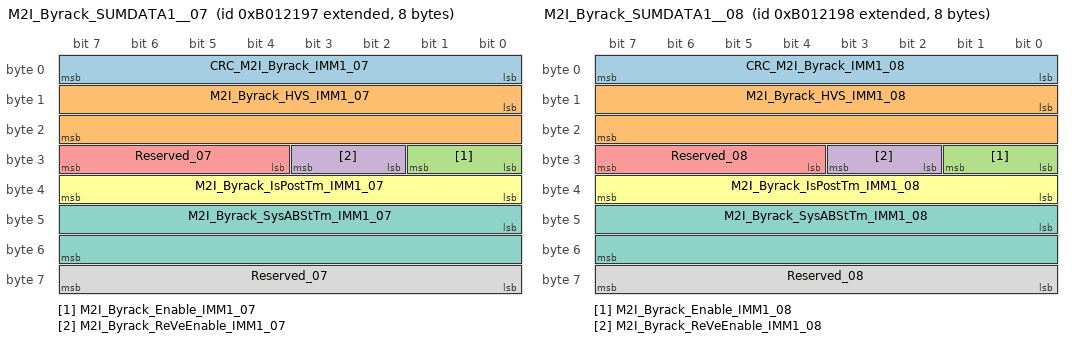
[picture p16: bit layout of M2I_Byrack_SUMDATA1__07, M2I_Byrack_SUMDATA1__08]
BO_ 2332107159 M2I_Byrack_SUMDATA1__07: 8 MBMU
 SG_ CRC_M2I_Byrack_IMM1_07 : 0|8@1+ (1,0) [0|255] ""  IMM
 SG_ M2I_Byrack_HVS_IMM1_07 : 8|16@1+ (0.1,0) [0|6553.5] "v"  IMM
 SG_ M2I_Byrack_Enable_IMM1_07 : 24|2@1+ (1,0) [0|3] ""  IMM
 SG_ M2I_Byrack_ReVeEnable_IMM1_07 : 26|2@1+ (1,0) [0|3] ""  IMM
 SG_ Reserved_07 : 28|4@1+ (1,0) [0|15] ""  IMM
 SG_ M2I_Byrack_IsPostTm_IMM1_07 : 32|8@1+ (0.01,0) [0|2.55] "s"  IMM
 SG_ M2I_Byrack_SysABStTm_IMM1_07 : 40|16@1+ (0.01,0) [0|655.35] "s"  IMM
 SG_ Reserved_07 : 56|8@1+ (1,0) [0|255] ""  IMM

BO_ 2332107160 M2I_Byrack_SUMDATA1__08: 8 MBMU
 SG_ CRC_M2I_Byrack_IMM1_08 : 0|8@1+ (1,0) [0|255] ""  IMM
 SG_ M2I_Byrack_HVS_IMM1_08 : 8|16@1+ (0.1,0) [0|6553.5] "v"  IMM
 SG_ M2I_Byrack_Enable_IMM1_08 : 24|2@1+ (1,0) [0|3] ""  IMM
 SG_ M2I_Byrack_ReVeEnable_IMM1_08 : 26|2@1+ (1,0) [0|3] ""  IMM
 SG_ Reserved_08 : 28|4@1+ (1,0) [0|15] ""  IMM
 SG_ M2I_Byrack_IsPostTm_IMM1_08 : 32|8@1+ (0.01,0) [0|2.55] "s"  IMM
 SG_ M2I_Byrack_SysABStTm_IMM1_08 : 40|16@1+ (0.01,0) [0|655.35] "s"  IMM
 SG_ Reserved_08 : 56|8@1+ (1,0) [0|255] ""  IMM

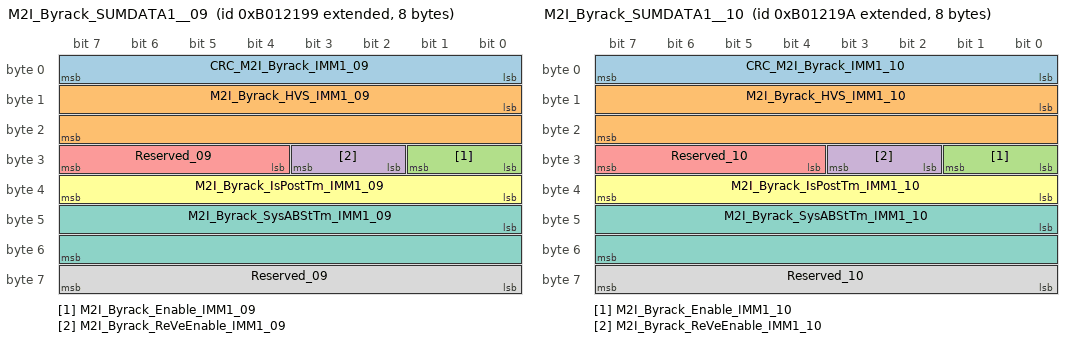
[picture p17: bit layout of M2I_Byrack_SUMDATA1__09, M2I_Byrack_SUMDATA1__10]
BO_ 2332107161 M2I_Byrack_SUMDATA1__09: 8 MBMU
 SG_ CRC_M2I_Byrack_IMM1_09 : 0|8@1+ (1,0) [0|255] ""  IMM
 SG_ M2I_Byrack_HVS_IMM1_09 : 8|16@1+ (0.1,0) [0|6553.5] "v"  IMM
 SG_ M2I_Byrack_Enable_IMM1_09 : 24|2@1+ (1,0) [0|3] ""  IMM
 SG_ M2I_Byrack_ReVeEnable_IMM1_09 : 26|2@1+ (1,0) [0|3] ""  IMM
 SG_ Reserved_09 : 28|4@1+ (1,0) [0|15] ""  IMM
 SG_ M2I_Byrack_IsPostTm_IMM1_09 : 32|8@1+ (0.01,0) [0|2.55] "s"  IMM
 SG_ M2I_Byrack_SysABStTm_IMM1_09 : 40|16@1+ (0.01,0) [0|655.35] "s"  IMM
 SG_ Reserved_09 : 56|8@1+ (1,0) [0|255] ""  IMM

BO_ 2332107162 M2I_Byrack_SUMDATA1__10: 8 MBMU
 SG_ CRC_M2I_Byrack_IMM1_10 : 0|8@1+ (1,0) [0|255] ""  IMM
 SG_ M2I_Byrack_HVS_IMM1_10 : 8|16@1+ (0.1,0) [0|6553.5] "v"  IMM
 SG_ M2I_Byrack_Enable_IMM1_10 : 24|2@1+ (1,0) [0|3] ""  IMM
 SG_ M2I_Byrack_ReVeEnable_IMM1_10 : 26|2@1+ (1,0) [0|3] ""  IMM
 SG_ Reserved_10 : 28|4@1+ (1,0) [0|15] ""  IMM
 SG_ M2I_Byrack_IsPostTm_IMM1_10 : 32|8@1+ (0.01,0) [0|2.55] "s"  IMM
 SG_ M2I_Byrack_SysABStTm_IMM1_10 : 40|16@1+ (0.01,0) [0|655.35] "s"  IMM
 SG_ Reserved_10 : 56|8@1+ (1,0) [0|255] ""  IMM

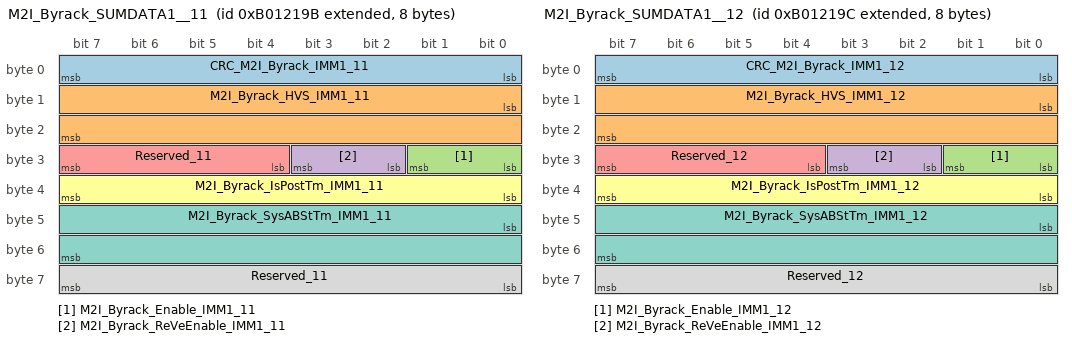
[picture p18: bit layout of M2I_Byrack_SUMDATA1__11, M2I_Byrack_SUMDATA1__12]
BO_ 2332107163 M2I_Byrack_SUMDATA1__11: 8 MBMU
 SG_ CRC_M2I_Byrack_IMM1_11 : 0|8@1+ (1,0) [0|255] ""  IMM
 SG_ M2I_Byrack_HVS_IMM1_11 : 8|16@1+ (0.1,0) [0|6553.5] "v"  IMM
 SG_ M2I_Byrack_Enable_IMM1_11 : 24|2@1+ (1,0) [0|3] ""  IMM
 SG_ M2I_Byrack_ReVeEnable_IMM1_11 : 26|2@1+ (1,0) [0|3] ""  IMM
 SG_ Reserved_11 : 28|4@1+ (1,0) [0|15] ""  IMM
 SG_ M2I_Byrack_IsPostTm_IMM1_11 : 32|8@1+ (0.01,0) [0|2.55] "s"  IMM
 SG_ M2I_Byrack_SysABStTm_IMM1_11 : 40|16@1+ (0.01,0) [0|655.35] "s"  IMM
 SG_ Reserved_11 : 56|8@1+ (1,0) [0|255] ""  IMM

BO_ 2332107164 M2I_Byrack_SUMDATA1__12: 8 MBMU
 SG_ CRC_M2I_Byrack_IMM1_12 : 0|8@1+ (1,0) [0|255] ""  IMM
 SG_ M2I_Byrack_HVS_IMM1_12 : 8|16@1+ (0.1,0) [0|6553.5] "v"  IMM
 SG_ M2I_Byrack_Enable_IMM1_12 : 24|2@1+ (1,0) [0|3] ""  IMM
 SG_ M2I_Byrack_ReVeEnable_IMM1_12 : 26|2@1+ (1,0) [0|3] ""  IMM
 SG_ Reserved_12 : 28|4@1+ (1,0) [0|15] ""  IMM
 SG_ M2I_Byrack_IsPostTm_IMM1_12 : 32|8@1+ (0.01,0) [0|2.55] "s"  IMM
 SG_ M2I_Byrack_SysABStTm_IMM1_12 : 40|16@1+ (0.01,0) [0|655.35] "s"  IMM
 SG_ Reserved_12 : 56|8@1+ (1,0) [0|255] ""  IMM

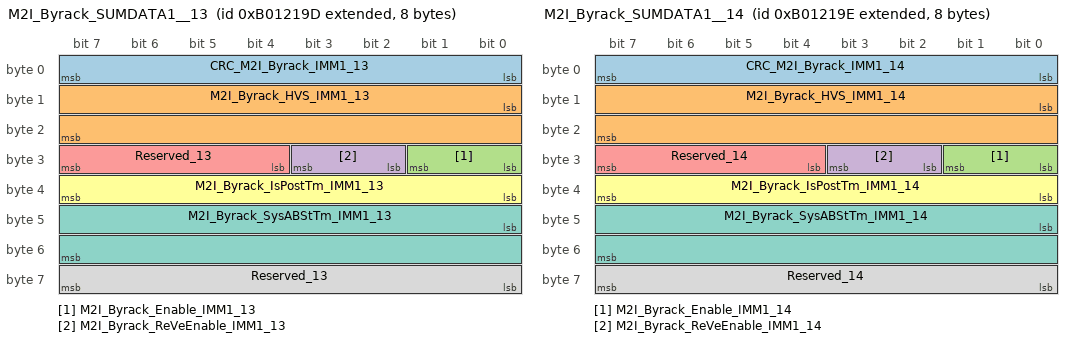
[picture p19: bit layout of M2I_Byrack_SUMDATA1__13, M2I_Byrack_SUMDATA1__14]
BO_ 2332107165 M2I_Byrack_SUMDATA1__13: 8 MBMU
 SG_ CRC_M2I_Byrack_IMM1_13 : 0|8@1+ (1,0) [0|255] ""  IMM
 SG_ M2I_Byrack_HVS_IMM1_13 : 8|16@1+ (0.1,0) [0|6553.5] "v"  IMM
 SG_ M2I_Byrack_Enable_IMM1_13 : 24|2@1+ (1,0) [0|3] ""  IMM
 SG_ M2I_Byrack_ReVeEnable_IMM1_13 : 26|2@1+ (1,0) [0|3] ""  IMM
 SG_ Reserved_13 : 28|4@1+ (1,0) [0|15] ""  IMM
 SG_ M2I_Byrack_IsPostTm_IMM1_13 : 32|8@1+ (0.01,0) [0|2.55] "s"  IMM
 SG_ M2I_Byrack_SysABStTm_IMM1_13 : 40|16@1+ (0.01,0) [0|655.35] "s"  IMM
 SG_ Reserved_13 : 56|8@1+ (1,0) [0|255] ""  IMM

BO_ 2332107166 M2I_Byrack_SUMDATA1__14: 8 MBMU
 SG_ CRC_M2I_Byrack_IMM1_14 : 0|8@1+ (1,0) [0|255] ""  IMM
 SG_ M2I_Byrack_HVS_IMM1_14 : 8|16@1+ (0.1,0) [0|6553.5] "v"  IMM
 SG_ M2I_Byrack_Enable_IMM1_14 : 24|2@1+ (1,0) [0|3] ""  IMM
 SG_ M2I_Byrack_ReVeEnable_IMM1_14 : 26|2@1+ (1,0) [0|3] ""  IMM
 SG_ Reserved_14 : 28|4@1+ (1,0) [0|15] ""  IMM
 SG_ M2I_Byrack_IsPostTm_IMM1_14 : 32|8@1+ (0.01,0) [0|2.55] "s"  IMM
 SG_ M2I_Byrack_SysABStTm_IMM1_14 : 40|16@1+ (0.01,0) [0|655.35] "s"  IMM
 SG_ Reserved_14 : 56|8@1+ (1,0) [0|255] ""  IMM

BO_ 2332107167 M2I_Byrack_SUMDATA1__15: 8 MBMU
 SG_ CRC_M2I_Byrack_IMM1_15 : 0|8@1+ (1,0) [0|255] ""  IMM
 SG_ M2I_Byrack_HVS_IMM1_15 : 8|16@1+ (0.1,0) [0|6553.5] "v"  IMM
 SG_ M2I_Byrack_Enable_IMM1_15 : 24|2@1+ (1,0) [0|3] ""  IMM
 SG_ M2I_Byrack_ReVeEnable_IMM1_15 : 26|2@1+ (1,0) [0|3] ""  IMM
 SG_ Reserved_15 : 28|4@1+ (1,0) [0|15] ""  IMM
 SG_ M2I_Byrack_IsPostTm_IMM1_15 : 32|8@1+ (0.01,0) [0|2.55] "s"  IMM
 SG_ M2I_Byrack_SysABStTm_IMM1_15 : 40|16@1+ (0.01,0) [0|655.35] "s"  IMM
 SG_ Reserved_15 : 56|8@1+ (1,0) [0|255] ""  IMM

BO_ 2332107168 M2I_Byrack_SUMDATA1__16: 8 MBMU
 SG_ CRC_M2I_Byrack_IMM1_16 : 0|8@1+ (1,0) [0|255] ""  IMM
 SG_ M2I_Byrack_HVS_IMM1_16 : 8|16@1+ (0.1,0) [0|6553.5] "v"  IMM
 SG_ M2I_Byrack_Enable_IMM1_16 : 24|2@1+ (1,0) [0|3] ""  IMM
 SG_ M2I_Byrack_ReVeEnable_IMM1_16 : 26|2@1+ (1,0) [0|3] ""  IMM
 SG_ Reserved_16 : 28|4@1+ (1,0) [0|15] ""  IMM
 SG_ M2I_Byrack_IsPostTm_IMM1_16 : 32|8@1+ (0.01,0) [0|2.55] "s"  IMM
 SG_ M2I_Byrack_SysABStTm_IMM1_16 : 40|16@1+ (0.01,0) [0|655.35] "s"  IMM
 SG_ Reserved_16 : 56|8@1+ (1,0) [0|255] ""  IMM

BO_ 2332107169 M2I_Byrack_SUMDATA1__17: 8 MBMU
 SG_ CRC_M2I_Byrack_IMM1_17 : 0|8@1+ (1,0) [0|255] ""  IMM
 SG_ M2I_Byrack_HVS_IMM1_17 : 8|16@1+ (0.1,0) [0|6553.5] "v"  IMM
 SG_ M2I_Byrack_Enable_IMM1_17 : 24|2@1+ (1,0) [0|3] ""  IMM
 SG_ M2I_Byrack_ReVeEnable_IMM1_17 : 26|2@1+ (1,0) [0|3] ""  IMM
 SG_ Reserved_17 : 28|4@1+ (1,0) [0|15] ""  IMM
 SG_ M2I_Byrack_IsPostTm_IMM1_17 : 32|8@1+ (0.01,0) [0|2.55] "s"  IMM
 SG_ M2I_Byrack_SysABStTm_IMM1_17 : 40|16@1+ (0.01,0) [0|655.35] "s"  IMM
 SG_ Reserved_17 : 56|8@1+ (1,0) [0|255] ""  IMM

BO_ 2332107170 M2I_Byrack_SUMDATA1__18: 8 MBMU
 SG_ CRC_M2I_Byrack_IMM1_18 : 0|8@1+ (1,0) [0|255] ""  IMM
 SG_ M2I_Byrack_HVS_IMM1_18 : 8|16@1+ (0.1,0) [0|6553.5] "v"  IMM
 SG_ M2I_Byrack_Enable_IMM1_18 : 24|2@1+ (1,0) [0|3] ""  IMM
 SG_ M2I_Byrack_ReVeEnable_IMM1_18 : 26|2@1+ (1,0) [0|3] ""  IMM
 SG_ Reserved_18 : 28|4@1+ (1,0) [0|15] ""  IMM
 SG_ M2I_Byrack_IsPostTm_IMM1_18 : 32|8@1+ (0.01,0) [0|2.55] "s"  IMM
 SG_ M2I_Byrack_SysABStTm_IMM1_18 : 40|16@1+ (0.01,0) [0|655.35] "s"  IMM
 SG_ Reserved_18 : 56|8@1+ (1,0) [0|255] ""  IMM

BO_ 2332107171 M2I_Byrack_SUMDATA1__19: 8 MBMU
 SG_ CRC_M2I_Byrack_IMM1_19 : 0|8@1+ (1,0) [0|255] ""  IMM
 SG_ M2I_Byrack_HVS_IMM1_19 : 8|16@1+ (0.1,0) [0|6553.5] "v"  IMM
 SG_ M2I_Byrack_Enable_IMM1_19 : 24|2@1+ (1,0) [0|3] ""  IMM
 SG_ M2I_Byrack_ReVeEnable_IMM1_19 : 26|2@1+ (1,0) [0|3] ""  IMM
 SG_ Reserved_19 : 28|4@1+ (1,0) [0|15] ""  IMM
 SG_ M2I_Byrack_IsPostTm_IMM1_19 : 32|8@1+ (0.01,0) [0|2.55] "s"  IMM
 SG_ M2I_Byrack_SysABStTm_IMM1_19 : 40|16@1+ (0.01,0) [0|655.35] "s"  IMM
 SG_ Reserved_19 : 56|8@1+ (1,0) [0|255] ""  IMM

BO_ 2332107172 M2I_Byrack_SUMDATA1__20: 8 MBMU
 SG_ CRC_M2I_Byrack_IMM1_20 : 0|8@1+ (1,0) [0|255] ""  IMM
 SG_ M2I_Byrack_HVS_IMM1_20 : 8|16@1+ (0.1,0) [0|6553.5] "v"  IMM
 SG_ M2I_Byrack_Enable_IMM1_20 : 24|2@1+ (1,0) [0|3] ""  IMM
 SG_ M2I_Byrack_ReVeEnable_IMM1_20 : 26|2@1+ (1,0) [0|3] ""  IMM
 SG_ Reserved_20 : 28|4@1+ (1,0) [0|15] ""  IMM
 SG_ M2I_Byrack_IsPostTm_IMM1_20 : 32|8@1+ (0.01,0) [0|2.55] "s"  IMM
 SG_ M2I_Byrack_SysABStTm_IMM1_20 : 40|16@1+ (0.01,0) [0|655.35] "s"  IMM
 SG_ Reserved_20 : 56|8@1+ (1,0) [0|255] ""  IMM

BO_ 2332107173 M2I_Byrack_SUMDATA1__21: 8 MBMU
 SG_ CRC_M2I_Byrack_IMM1_21 : 0|8@1+ (1,0) [0|255] ""  IMM
 SG_ M2I_Byrack_HVS_IMM1_21 : 8|16@1+ (0.1,0) [0|6553.5] "v"  IMM
 SG_ M2I_Byrack_Enable_IMM1_21 : 24|2@1+ (1,0) [0|3] ""  IMM
 SG_ M2I_Byrack_ReVeEnable_IMM1_21 : 26|2@1+ (1,0) [0|3] ""  IMM
 SG_ Reserved_21 : 28|4@1+ (1,0) [0|15] ""  IMM
 SG_ M2I_Byrack_IsPostTm_IMM1_21 : 32|8@1+ (0.01,0) [0|2.55] "s"  IMM
 SG_ M2I_Byrack_SysABStTm_IMM1_21 : 40|16@1+ (0.01,0) [0|655.35] "s"  IMM
 SG_ Reserved_21 : 56|8@1+ (1,0) [0|255] ""  IMM

BO_ 2332107174 M2I_Byrack_SUMDATA1__22: 8 MBMU
 SG_ CRC_M2I_Byrack_IMM1_22 : 0|8@1+ (1,0) [0|255] ""  IMM
 SG_ M2I_Byrack_HVS_IMM1_22 : 8|16@1+ (0.1,0) [0|6553.5] "v"  IMM
 SG_ M2I_Byrack_Enable_IMM1_22 : 24|2@1+ (1,0) [0|3] ""  IMM
 SG_ M2I_Byrack_ReVeEnable_IMM1_22 : 26|2@1+ (1,0) [0|3] ""  IMM
 SG_ Reserved_22 : 28|4@1+ (1,0) [0|15] ""  IMM
 SG_ M2I_Byrack_IsPostTm_IMM1_22 : 32|8@1+ (0.01,0) [0|2.55] "s"  IMM
 SG_ M2I_Byrack_SysABStTm_IMM1_22 : 40|16@1+ (0.01,0) [0|655.35] "s"  IMM
 SG_ Reserved_22 : 56|8@1+ (1,0) [0|255] ""  IMM

BO_ 2332107175 M2I_Byrack_SUMDATA1__23: 8 MBMU
 SG_ CRC_M2I_Byrack_IMM1_23 : 0|8@1+ (1,0) [0|255] ""  IMM
 SG_ M2I_Byrack_HVS_IMM1_23 : 8|16@1+ (0.1,0) [0|6553.5] "v"  IMM
 SG_ M2I_Byrack_Enable_IMM1_23 : 24|2@1+ (1,0) [0|3] ""  IMM
 SG_ M2I_Byrack_ReVeEnable_IMM1_23 : 26|2@1+ (1,0) [0|3] ""  IMM
 SG_ Reserved_23 : 28|4@1+ (1,0) [0|15] ""  IMM
 SG_ M2I_Byrack_IsPostTm_IMM1_23 : 32|8@1+ (0.01,0) [0|2.55] "s"  IMM
 SG_ M2I_Byrack_SysABStTm_IMM1_23 : 40|16@1+ (0.01,0) [0|655.35] "s"  IMM
 SG_ Reserved_23 : 56|8@1+ (1,0) [0|255] ""  IMM

BO_ 2332107176 M2I_Byrack_SUMDATA1__24: 8 MBMU
 SG_ CRC_M2I_Byrack_IMM1_24 : 0|8@1+ (1,0) [0|255] ""  IMM
 SG_ M2I_Byrack_HVS_IMM1_24 : 8|16@1+ (0.1,0) [0|6553.5] "v"  IMM
 SG_ M2I_Byrack_Enable_IMM1_24 : 24|2@1+ (1,0) [0|3] ""  IMM
 SG_ M2I_Byrack_ReVeEnable_IMM1_24 : 26|2@1+ (1,0) [0|3] ""  IMM
 SG_ Reserved_24 : 28|4@1+ (1,0) [0|15] ""  IMM
 SG_ M2I_Byrack_IsPostTm_IMM1_24 : 32|8@1+ (0.01,0) [0|2.55] "s"  IMM
 SG_ M2I_Byrack_SysABStTm_IMM1_24 : 40|16@1+ (0.01,0) [0|655.35] "s"  IMM
 SG_ Reserved_24 : 56|8@1+ (1,0) [0|255] ""  IMM

BO_ 2332107177 M2I_Byrack_SUMDATA1__25: 8 MBMU
 SG_ CRC_M2I_Byrack_IMM1_25 : 0|8@1+ (1,0) [0|255] ""  IMM
 SG_ M2I_Byrack_HVS_IMM1_25 : 8|16@1+ (0.1,0) [0|6553.5] "v"  IMM
 SG_ M2I_Byrack_Enable_IMM1_25 : 24|2@1+ (1,0) [0|3] ""  IMM
 SG_ M2I_Byrack_ReVeEnable_IMM1_25 : 26|2@1+ (1,0) [0|3] ""  IMM
 SG_ Reserved_25 : 28|4@1+ (1,0) [0|15] ""  IMM
 SG_ M2I_Byrack_IsPostTm_IMM1_25 : 32|8@1+ (0.01,0) [0|2.55] "s"  IMM
 SG_ M2I_Byrack_SysABStTm_IMM1_25 : 40|16@1+ (0.01,0) [0|655.35] "s"  IMM
 SG_ Reserved_25 : 56|8@1+ (1,0) [0|255] ""  IMM

BO_ 2332107178 M2I_Byrack_SUMDATA1__26: 8 MBMU
 SG_ CRC_M2I_Byrack_IMM1_26 : 0|8@1+ (1,0) [0|255] ""  IMM
 SG_ M2I_Byrack_HVS_IMM1_26 : 8|16@1+ (0.1,0) [0|6553.5] "v"  IMM
 SG_ M2I_Byrack_Enable_IMM1_26 : 24|2@1+ (1,0) [0|3] ""  IMM
 SG_ M2I_Byrack_ReVeEnable_IMM1_26 : 26|2@1+ (1,0) [0|3] ""  IMM
 SG_ Reserved_26 : 28|4@1+ (1,0) [0|15] ""  IMM
 SG_ M2I_Byrack_IsPostTm_IMM1_26 : 32|8@1+ (0.01,0) [0|2.55] "s"  IMM
 SG_ M2I_Byrack_SysABStTm_IMM1_26 : 40|16@1+ (0.01,0) [0|655.35] "s"  IMM
 SG_ Reserved_26 : 56|8@1+ (1,0) [0|255] ""  IMM

BO_ 2332107179 M2I_Byrack_SUMDATA1__27: 8 MBMU
 SG_ CRC_M2I_Byrack_IMM1_27 : 0|8@1+ (1,0) [0|255] ""  IMM
 SG_ M2I_Byrack_HVS_IMM1_27 : 8|16@1+ (0.1,0) [0|6553.5] "v"  IMM
 SG_ M2I_Byrack_Enable_IMM1_27 : 24|2@1+ (1,0) [0|3] ""  IMM
 SG_ M2I_Byrack_ReVeEnable_IMM1_27 : 26|2@1+ (1,0) [0|3] ""  IMM
 SG_ Reserved_27 : 28|4@1+ (1,0) [0|15] ""  IMM
 SG_ M2I_Byrack_IsPostTm_IMM1_27 : 32|8@1+ (0.01,0) [0|2.55] "s"  IMM
 SG_ M2I_Byrack_SysABStTm_IMM1_27 : 40|16@1+ (0.01,0) [0|655.35] "s"  IMM
 SG_ Reserved_27 : 56|8@1+ (1,0) [0|255] ""  IMM

BO_ 2332107180 M2I_Byrack_SUMDATA1__28: 8 MBMU
 SG_ CRC_M2I_Byrack_IMM1_28 : 0|8@1+ (1,0) [0|255] ""  IMM
 SG_ M2I_Byrack_HVS_IMM1_28 : 8|16@1+ (0.1,0) [0|6553.5] "v"  IMM
 SG_ M2I_Byrack_Enable_IMM1_28 : 24|2@1+ (1,0) [0|3] ""  IMM
 SG_ M2I_Byrack_ReVeEnable_IMM1_28 : 26|2@1+ (1,0) [0|3] ""  IMM
 SG_ Reserved_28 : 28|4@1+ (1,0) [0|15] ""  IMM
 SG_ M2I_Byrack_IsPostTm_IMM1_28 : 32|8@1+ (0.01,0) [0|2.55] "s"  IMM
 SG_ M2I_Byrack_SysABStTm_IMM1_28 : 40|16@1+ (0.01,0) [0|655.35] "s"  IMM
 SG_ Reserved_28 : 56|8@1+ (1,0) [0|255] ""  IMM

BO_ 2332107181 M2I_Byrack_SUMDATA1__29: 8 MBMU
 SG_ CRC_M2I_Byrack_IMM1_29 : 0|8@1+ (1,0) [0|255] ""  IMM
 SG_ M2I_Byrack_HVS_IMM1_29 : 8|16@1+ (0.1,0) [0|6553.5] "v"  IMM
 SG_ M2I_Byrack_Enable_IMM1_29 : 24|2@1+ (1,0) [0|3] ""  IMM
 SG_ M2I_Byrack_ReVeEnable_IMM1_29 : 26|2@1+ (1,0) [0|3] ""  IMM
 SG_ Reserved_29 : 28|4@1+ (1,0) [0|15] ""  IMM
 SG_ M2I_Byrack_IsPostTm_IMM1_29 : 32|8@1+ (0.01,0) [0|2.55] "s"  IMM
 SG_ M2I_Byrack_SysABStTm_IMM1_29 : 40|16@1+ (0.01,0) [0|655.35] "s"  IMM
 SG_ Reserved_29 : 56|8@1+ (1,0) [0|255] ""  IMM

BO_ 2332107182 M2I_Byrack_SUMDATA1__30: 8 MBMU
 SG_ CRC_M2I_Byrack_IMM1_30 : 0|8@1+ (1,0) [0|255] ""  IMM
 SG_ M2I_Byrack_HVS_IMM1_30 : 8|16@1+ (0.1,0) [0|6553.5] "v"  IMM
 SG_ M2I_Byrack_Enable_IMM1_30 : 24|2@1+ (1,0) [0|3] ""  IMM
 SG_ M2I_Byrack_ReVeEnable_IMM1_30 : 26|2@1+ (1,0) [0|3] ""  IMM
 SG_ Reserved_30 : 28|4@1+ (1,0) [0|15] ""  IMM
 SG_ M2I_Byrack_IsPostTm_IMM1_30 : 32|8@1+ (0.01,0) [0|2.55] "s"  IMM
 SG_ M2I_Byrack_SysABStTm_IMM1_30 : 40|16@1+ (0.01,0) [0|655.35] "s"  IMM
 SG_ Reserved_30 : 56|8@1+ (1,0) [0|255] ""  IMM

BO_ 2332107183 M2I_Byrack_SUMDATA1__31: 8 MBMU
 SG_ CRC_M2I_Byrack_IMM1_31 : 0|8@1+ (1,0) [0|255] ""  IMM
 SG_ M2I_Byrack_HVS_IMM1_31 : 8|16@1+ (0.1,0) [0|6553.5] "v"  IMM
 SG_ M2I_Byrack_Enable_IMM1_31 : 24|2@1+ (1,0) [0|3] ""  IMM
 SG_ M2I_Byrack_ReVeEnable_IMM1_31 : 26|2@1+ (1,0) [0|3] ""  IMM
 SG_ Reserved_31 : 28|4@1+ (1,0) [0|15] ""  IMM
 SG_ M2I_Byrack_IsPostTm_IMM1_31 : 32|8@1+ (0.01,0) [0|2.55] "s"  IMM
 SG_ M2I_Byrack_SysABStTm_IMM1_31 : 40|16@1+ (0.01,0) [0|655.35] "s"  IMM
 SG_ Reserved_31 : 56|8@1+ (1,0) [0|255] ""  IMM

BO_ 2332107409 M2I_Byrack_SUMDATA2__01: 8 MBMU
 SG_ CRC_M2I_Byrack_IMM2_01 : 0|8@1+ (1,0) [0|255] ""  IMM
 SG_ M2I_Byrack_HVS_IMM2_01 : 8|16@1+ (0.1,0) [0|6553.5] "v"  IMM
 SG_ M2I_Byrack_Enable_IMM2_01 : 24|2@1+ (1,0) [0|3] ""  IMM
 SG_ M2I_Byrack_ReVeEnable_IMM2_01 : 26|2@1+ (1,0) [0|3] ""  IMM
 SG_ Reserved_01 : 28|4@1+ (1,0) [0|15] ""  IMM
 SG_ M2I_Byrack_IsPostTm_IMM2_01 : 32|8@1+ (0.01,0) [0|2.55] "s"  IMM
 SG_ M2I_Byrack_SysABStTm_IMM2_01 : 40|16@1+ (0.01,0) [0|655.35] "s"  IMM
 SG_ Reserved_01 : 56|8@1+ (1,0) [0|255] ""  IMM

BO_ 2332107410 M2I_Byrack_SUMDATA2__02: 8 MBMU
 SG_ CRC_M2I_Byrack_IMM2_02 : 0|8@1+ (1,0) [0|255] ""  IMM
 SG_ M2I_Byrack_HVS_IMM2_02 : 8|16@1+ (0.1,0) [0|6553.5] "v"  IMM
 SG_ M2I_Byrack_Enable_IMM2_02 : 24|2@1+ (1,0) [0|3] ""  IMM
 SG_ M2I_Byrack_ReVeEnable_IMM2_02 : 26|2@1+ (1,0) [0|3] ""  IMM
 SG_ Reserved_02 : 28|4@1+ (1,0) [0|15] ""  IMM
 SG_ M2I_Byrack_IsPostTm_IMM2_02 : 32|8@1+ (0.01,0) [0|2.55] "s"  IMM
 SG_ M2I_Byrack_SysABStTm_IMM2_02 : 40|16@1+ (0.01,0) [0|655.35] "s"  IMM
 SG_ Reserved_02 : 56|8@1+ (1,0) [0|255] ""  IMM

BO_ 2332107411 M2I_Byrack_SUMDATA2__03: 8 MBMU
 SG_ CRC_M2I_Byrack_IMM2_03 : 0|8@1+ (1,0) [0|255] ""  IMM
 SG_ M2I_Byrack_HVS_IMM2_03 : 8|16@1+ (0.1,0) [0|6553.5] "v"  IMM
 SG_ M2I_Byrack_Enable_IMM2_03 : 24|2@1+ (1,0) [0|3] ""  IMM
 SG_ M2I_Byrack_ReVeEnable_IMM2_03 : 26|2@1+ (1,0) [0|3] ""  IMM
 SG_ Reserved_03 : 28|4@1+ (1,0) [0|15] ""  IMM
 SG_ M2I_Byrack_IsPostTm_IMM2_03 : 32|8@1+ (0.01,0) [0|2.55] "s"  IMM
 SG_ M2I_Byrack_SysABStTm_IMM2_03 : 40|16@1+ (0.01,0) [0|655.35] "s"  IMM
 SG_ Reserved_03 : 56|8@1+ (1,0) [0|255] ""  IMM

BO_ 2332107412 M2I_Byrack_SUMDATA2__04: 8 MBMU
 SG_ CRC_M2I_Byrack_IMM2_04 : 0|8@1+ (1,0) [0|255] ""  IMM
 SG_ M2I_Byrack_HVS_IMM2_04 : 8|16@1+ (0.1,0) [0|6553.5] "v"  IMM
 SG_ M2I_Byrack_Enable_IMM2_04 : 24|2@1+ (1,0) [0|3] ""  IMM
 SG_ M2I_Byrack_ReVeEnable_IMM2_04 : 26|2@1+ (1,0) [0|3] ""  IMM
 SG_ Reserved_04 : 28|4@1+ (1,0) [0|15] ""  IMM
 SG_ M2I_Byrack_IsPostTm_IMM2_04 : 32|8@1+ (0.01,0) [0|2.55] "s"  IMM
 SG_ M2I_Byrack_SysABStTm_IMM2_04 : 40|16@1+ (0.01,0) [0|655.35] "s"  IMM
 SG_ Reserved_04 : 56|8@1+ (1,0) [0|255] ""  IMM

BO_ 2332107413 M2I_Byrack_SUMDATA2__05: 8 MBMU
 SG_ CRC_M2I_Byrack_IMM2_05 : 0|8@1+ (1,0) [0|255] ""  IMM
 SG_ M2I_Byrack_HVS_IMM2_05 : 8|16@1+ (0.1,0) [0|6553.5] "v"  IMM
 SG_ M2I_Byrack_Enable_IMM2_05 : 24|2@1+ (1,0) [0|3] ""  IMM
 SG_ M2I_Byrack_ReVeEnable_IMM2_05 : 26|2@1+ (1,0) [0|3] ""  IMM
 SG_ Reserved_05 : 28|4@1+ (1,0) [0|15] ""  IMM
 SG_ M2I_Byrack_IsPostTm_IMM2_05 : 32|8@1+ (0.01,0) [0|2.55] "s"  IMM
 SG_ M2I_Byrack_SysABStTm_IMM2_05 : 40|16@1+ (0.01,0) [0|655.35] "s"  IMM
 SG_ Reserved_05 : 56|8@1+ (1,0) [0|255] ""  IMM

BO_ 2332107414 M2I_Byrack_SUMDATA2__06: 8 MBMU
 SG_ CRC_M2I_Byrack_IMM2_06 : 0|8@1+ (1,0) [0|255] ""  IMM
 SG_ M2I_Byrack_HVS_IMM2_06 : 8|16@1+ (0.1,0) [0|6553.5] "v"  IMM
 SG_ M2I_Byrack_Enable_IMM2_06 : 24|2@1+ (1,0) [0|3] ""  IMM
 SG_ M2I_Byrack_ReVeEnable_IMM2_06 : 26|2@1+ (1,0) [0|3] ""  IMM
 SG_ Reserved_06 : 28|4@1+ (1,0) [0|15] ""  IMM
 SG_ M2I_Byrack_IsPostTm_IMM2_06 : 32|8@1+ (0.01,0) [0|2.55] "s"  IMM
 SG_ M2I_Byrack_SysABStTm_IMM2_06 : 40|16@1+ (0.01,0) [0|655.35] "s"  IMM
 SG_ Reserved_06 : 56|8@1+ (1,0) [0|255] ""  IMM

BO_ 2332107415 M2I_Byrack_SUMDATA2__07: 8 MBMU
 SG_ CRC_M2I_Byrack_IMM2_07 : 0|8@1+ (1,0) [0|255] ""  IMM
 SG_ M2I_Byrack_HVS_IMM2_07 : 8|16@1+ (0.1,0) [0|6553.5] "v"  IMM
 SG_ M2I_Byrack_Enable_IMM2_07 : 24|2@1+ (1,0) [0|3] ""  IMM
 SG_ M2I_Byrack_ReVeEnable_IMM2_07 : 26|2@1+ (1,0) [0|3] ""  IMM
 SG_ Reserved_07 : 28|4@1+ (1,0) [0|15] ""  IMM
 SG_ M2I_Byrack_IsPostTm_IMM2_07 : 32|8@1+ (0.01,0) [0|2.55] "s"  IMM
 SG_ M2I_Byrack_SysABStTm_IMM2_07 : 40|16@1+ (0.01,0) [0|655.35] "s"  IMM
 SG_ Reserved_07 : 56|8@1+ (1,0) [0|255] ""  IMM

BO_ 2332107416 M2I_Byrack_SUMDATA2__08: 8 MBMU
 SG_ CRC_M2I_Byrack_IMM2_08 : 0|8@1+ (1,0) [0|255] ""  IMM
 SG_ M2I_Byrack_HVS_IMM2_08 : 8|16@1+ (0.1,0) [0|6553.5] "v"  IMM
 SG_ M2I_Byrack_Enable_IMM2_08 : 24|2@1+ (1,0) [0|3] ""  IMM
 SG_ M2I_Byrack_ReVeEnable_IMM2_08 : 26|2@1+ (1,0) [0|3] ""  IMM
 SG_ Reserved_08 : 28|4@1+ (1,0) [0|15] ""  IMM
 SG_ M2I_Byrack_IsPostTm_IMM2_08 : 32|8@1+ (0.01,0) [0|2.55] "s"  IMM
 SG_ M2I_Byrack_SysABStTm_IMM2_08 : 40|16@1+ (0.01,0) [0|655.35] "s"  IMM
 SG_ Reserved_08 : 56|8@1+ (1,0) [0|255] ""  IMM

BO_ 2332107417 M2I_Byrack_SUMDATA2__09: 8 MBMU
 SG_ CRC_M2I_Byrack_IMM2_09 : 0|8@1+ (1,0) [0|255] ""  IMM
 SG_ M2I_Byrack_HVS_IMM2_09 : 8|16@1+ (0.1,0) [0|6553.5] "v"  IMM
 SG_ M2I_Byrack_Enable_IMM2_09 : 24|2@1+ (1,0) [0|3] ""  IMM
 SG_ M2I_Byrack_ReVeEnable_IMM2_09 : 26|2@1+ (1,0) [0|3] ""  IMM
 SG_ Reserved_09 : 28|4@1+ (1,0) [0|15] ""  IMM
 SG_ M2I_Byrack_IsPostTm_IMM2_09 : 32|8@1+ (0.01,0) [0|2.55] "s"  IMM
 SG_ M2I_Byrack_SysABStTm_IMM2_09 : 40|16@1+ (0.01,0) [0|655.35] "s"  IMM
 SG_ Reserved_09 : 56|8@1+ (1,0) [0|255] ""  IMM

BO_ 2332107418 M2I_Byrack_SUMDATA2__10: 8 MBMU
 SG_ CRC_M2I_Byrack_IMM2_10 : 0|8@1+ (1,0) [0|255] ""  IMM
 SG_ M2I_Byrack_HVS_IMM2_10 : 8|16@1+ (0.1,0) [0|6553.5] "v"  IMM
 SG_ M2I_Byrack_Enable_IMM2_10 : 24|2@1+ (1,0) [0|3] ""  IMM
 SG_ M2I_Byrack_ReVeEnable_IMM2_10 : 26|2@1+ (1,0) [0|3] ""  IMM
 SG_ Reserved_10 : 28|4@1+ (1,0) [0|15] ""  IMM
 SG_ M2I_Byrack_IsPostTm_IMM2_10 : 32|8@1+ (0.01,0) [0|2.55] "s"  IMM
 SG_ M2I_Byrack_SysABStTm_IMM2_10 : 40|16@1+ (0.01,0) [0|655.35] "s"  IMM
 SG_ Reserved_10 : 56|8@1+ (1,0) [0|255] ""  IMM

BO_ 2332107419 M2I_Byrack_SUMDATA2__11: 8 MBMU
 SG_ CRC_M2I_Byrack_IMM2_11 : 0|8@1+ (1,0) [0|255] ""  IMM
 SG_ M2I_Byrack_HVS_IMM2_11 : 8|16@1+ (0.1,0) [0|6553.5] "v"  IMM
 SG_ M2I_Byrack_Enable_IMM2_11 : 24|2@1+ (1,0) [0|3] ""  IMM
 SG_ M2I_Byrack_ReVeEnable_IMM2_11 : 26|2@1+ (1,0) [0|3] ""  IMM
 SG_ Reserved_11 : 28|4@1+ (1,0) [0|15] ""  IMM
 SG_ M2I_Byrack_IsPostTm_IMM2_11 : 32|8@1+ (0.01,0) [0|2.55] "s"  IMM
 SG_ M2I_Byrack_SysABStTm_IMM2_11 : 40|16@1+ (0.01,0) [0|655.35] "s"  IMM
 SG_ Reserved_11 : 56|8@1+ (1,0) [0|255] ""  IMM

BO_ 2332107420 M2I_Byrack_SUMDATA2__12: 8 MBMU
 SG_ CRC_M2I_Byrack_IMM2_12 : 0|8@1+ (1,0) [0|255] ""  IMM
 SG_ M2I_Byrack_HVS_IMM2_12 : 8|16@1+ (0.1,0) [0|6553.5] "v"  IMM
 SG_ M2I_Byrack_Enable_IMM2_12 : 24|2@1+ (1,0) [0|3] ""  IMM
 SG_ M2I_Byrack_ReVeEnable_IMM2_12 : 26|2@1+ (1,0) [0|3] ""  IMM
 SG_ Reserved_12 : 28|4@1+ (1,0) [0|15] ""  IMM
 SG_ M2I_Byrack_IsPostTm_IMM2_12 : 32|8@1+ (0.01,0) [0|2.55] "s"  IMM
 SG_ M2I_Byrack_SysABStTm_IMM2_12 : 40|16@1+ (0.01,0) [0|655.35] "s"  IMM
 SG_ Reserved_12 : 56|8@1+ (1,0) [0|255] ""  IMM

BO_ 2332107421 M2I_Byrack_SUMDATA2__13: 8 MBMU
 SG_ CRC_M2I_Byrack_IMM2_13 : 0|8@1+ (1,0) [0|255] ""  IMM
 SG_ M2I_Byrack_HVS_IMM2_13 : 8|16@1+ (0.1,0) [0|6553.5] "v"  IMM
 SG_ M2I_Byrack_Enable_IMM2_13 : 24|2@1+ (1,0) [0|3] ""  IMM
 SG_ M2I_Byrack_ReVeEnable_IMM2_13 : 26|2@1+ (1,0) [0|3] ""  IMM
 SG_ Reserved_13 : 28|4@1+ (1,0) [0|15] ""  IMM
 SG_ M2I_Byrack_IsPostTm_IMM2_13 : 32|8@1+ (0.01,0) [0|2.55] "s"  IMM
 SG_ M2I_Byrack_SysABStTm_IMM2_13 : 40|16@1+ (0.01,0) [0|655.35] "s"  IMM
 SG_ Reserved_13 : 56|8@1+ (1,0) [0|255] ""  IMM

BO_ 2332107422 M2I_Byrack_SUMDATA2__14: 8 MBMU
 SG_ CRC_M2I_Byrack_IMM2_14 : 0|8@1+ (1,0) [0|255] ""  IMM
 SG_ M2I_Byrack_HVS_IMM2_14 : 8|16@1+ (0.1,0) [0|6553.5] "v"  IMM
 SG_ M2I_Byrack_Enable_IMM2_14 : 24|2@1+ (1,0) [0|3] ""  IMM
 SG_ M2I_Byrack_ReVeEnable_IMM2_14 : 26|2@1+ (1,0) [0|3] ""  IMM
 SG_ Reserved_14 : 28|4@1+ (1,0) [0|15] ""  IMM
 SG_ M2I_Byrack_IsPostTm_IMM2_14 : 32|8@1+ (0.01,0) [0|2.55] "s"  IMM
 SG_ M2I_Byrack_SysABStTm_IMM2_14 : 40|16@1+ (0.01,0) [0|655.35] "s"  IMM
 SG_ Reserved_14 : 56|8@1+ (1,0) [0|255] ""  IMM

BO_ 2332107423 M2I_Byrack_SUMDATA2__15: 8 MBMU
 SG_ CRC_M2I_Byrack_IMM2_15 : 0|8@1+ (1,0) [0|255] ""  IMM
 SG_ M2I_Byrack_HVS_IMM2_15 : 8|16@1+ (0.1,0) [0|6553.5] "v"  IMM
 SG_ M2I_Byrack_Enable_IMM2_15 : 24|2@1+ (1,0) [0|3] ""  IMM
 SG_ M2I_Byrack_ReVeEnable_IMM2_15 : 26|2@1+ (1,0) [0|3] ""  IMM
 SG_ Reserved_15 : 28|4@1+ (1,0) [0|15] ""  IMM
 SG_ M2I_Byrack_IsPostTm_IMM2_15 : 32|8@1+ (0.01,0) [0|2.55] "s"  IMM
 SG_ M2I_Byrack_SysABStTm_IMM2_15 : 40|16@1+ (0.01,0) [0|655.35] "s"  IMM
 SG_ Reserved_15 : 56|8@1+ (1,0) [0|255] ""  IMM

BO_ 2332107424 M2I_Byrack_SUMDATA2__16: 8 MBMU
 SG_ CRC_M2I_Byrack_IMM2_16 : 0|8@1+ (1,0) [0|255] ""  IMM
 SG_ M2I_Byrack_HVS_IMM2_16 : 8|16@1+ (0.1,0) [0|6553.5] "v"  IMM
 SG_ M2I_Byrack_Enable_IMM2_16 : 24|2@1+ (1,0) [0|3] ""  IMM
 SG_ M2I_Byrack_ReVeEnable_IMM2_16 : 26|2@1+ (1,0) [0|3] ""  IMM
 SG_ Reserved_16 : 28|4@1+ (1,0) [0|15] ""  IMM
 SG_ M2I_Byrack_IsPostTm_IMM2_16 : 32|8@1+ (0.01,0) [0|2.55] "s"  IMM
 SG_ M2I_Byrack_SysABStTm_IMM2_16 : 40|16@1+ (0.01,0) [0|655.35] "s"  IMM
 SG_ Reserved_16 : 56|8@1+ (1,0) [0|255] ""  IMM

BO_ 2332107425 M2I_Byrack_SUMDATA2__17: 8 MBMU
 SG_ CRC_M2I_Byrack_IMM2_17 : 0|8@1+ (1,0) [0|255] ""  IMM
 SG_ M2I_Byrack_HVS_IMM2_17 : 8|16@1+ (0.1,0) [0|6553.5] "v"  IMM
 SG_ M2I_Byrack_Enable_IMM2_17 : 24|2@1+ (1,0) [0|3] ""  IMM
 SG_ M2I_Byrack_ReVeEnable_IMM2_17 : 26|2@1+ (1,0) [0|3] ""  IMM
 SG_ Reserved_17 : 28|4@1+ (1,0) [0|15] ""  IMM
 SG_ M2I_Byrack_IsPostTm_IMM2_17 : 32|8@1+ (0.01,0) [0|2.55] "s"  IMM
 SG_ M2I_Byrack_SysABStTm_IMM2_17 : 40|16@1+ (0.01,0) [0|655.35] "s"  IMM
 SG_ Reserved_17 : 56|8@1+ (1,0) [0|255] ""  IMM

BO_ 2332107426 M2I_Byrack_SUMDATA2__18: 8 MBMU
 SG_ CRC_M2I_Byrack_IMM2_18 : 0|8@1+ (1,0) [0|255] ""  IMM
 SG_ M2I_Byrack_HVS_IMM2_18 : 8|16@1+ (0.1,0) [0|6553.5] "v"  IMM
 SG_ M2I_Byrack_Enable_IMM2_18 : 24|2@1+ (1,0) [0|3] ""  IMM
 SG_ M2I_Byrack_ReVeEnable_IMM2_18 : 26|2@1+ (1,0) [0|3] ""  IMM
 SG_ Reserved_18 : 28|4@1+ (1,0) [0|15] ""  IMM
 SG_ M2I_Byrack_IsPostTm_IMM2_18 : 32|8@1+ (0.01,0) [0|2.55] "s"  IMM
 SG_ M2I_Byrack_SysABStTm_IMM2_18 : 40|16@1+ (0.01,0) [0|655.35] "s"  IMM
 SG_ Reserved_18 : 56|8@1+ (1,0) [0|255] ""  IMM

BO_ 2332107427 M2I_Byrack_SUMDATA2__19: 8 MBMU
 SG_ CRC_M2I_Byrack_IMM2_19 : 0|8@1+ (1,0) [0|255] ""  IMM
 SG_ M2I_Byrack_HVS_IMM2_19 : 8|16@1+ (0.1,0) [0|6553.5] "v"  IMM
 SG_ M2I_Byrack_Enable_IMM2_19 : 24|2@1+ (1,0) [0|3] ""  IMM
 SG_ M2I_Byrack_ReVeEnable_IMM2_19 : 26|2@1+ (1,0) [0|3] ""  IMM
 SG_ Reserved_19 : 28|4@1+ (1,0) [0|15] ""  IMM
 SG_ M2I_Byrack_IsPostTm_IMM2_19 : 32|8@1+ (0.01,0) [0|2.55] "s"  IMM
 SG_ M2I_Byrack_SysABStTm_IMM2_19 : 40|16@1+ (0.01,0) [0|655.35] "s"  IMM
 SG_ Reserved_19 : 56|8@1+ (1,0) [0|255] ""  IMM

BO_ 2332107428 M2I_Byrack_SUMDATA2__20: 8 MBMU
 SG_ CRC_M2I_Byrack_IMM2_20 : 0|8@1+ (1,0) [0|255] ""  IMM
 SG_ M2I_Byrack_HVS_IMM2_20 : 8|16@1+ (0.1,0) [0|6553.5] "v"  IMM
 SG_ M2I_Byrack_Enable_IMM2_20 : 24|2@1+ (1,0) [0|3] ""  IMM
 SG_ M2I_Byrack_ReVeEnable_IMM2_20 : 26|2@1+ (1,0) [0|3] ""  IMM
 SG_ Reserved_20 : 28|4@1+ (1,0) [0|15] ""  IMM
 SG_ M2I_Byrack_IsPostTm_IMM2_20 : 32|8@1+ (0.01,0) [0|2.55] "s"  IMM
 SG_ M2I_Byrack_SysABStTm_IMM2_20 : 40|16@1+ (0.01,0) [0|655.35] "s"  IMM
 SG_ Reserved_20 : 56|8@1+ (1,0) [0|255] ""  IMM

BO_ 2332107429 M2I_Byrack_SUMDATA2__21: 8 MBMU
 SG_ CRC_M2I_Byrack_IMM2_21 : 0|8@1+ (1,0) [0|255] ""  IMM
 SG_ M2I_Byrack_HVS_IMM2_21 : 8|16@1+ (0.1,0) [0|6553.5] "v"  IMM
 SG_ M2I_Byrack_Enable_IMM2_21 : 24|2@1+ (1,0) [0|3] ""  IMM
 SG_ M2I_Byrack_ReVeEnable_IMM2_21 : 26|2@1+ (1,0) [0|3] ""  IMM
 SG_ Reserved_21 : 28|4@1+ (1,0) [0|15] ""  IMM
 SG_ M2I_Byrack_IsPostTm_IMM2_21 : 32|8@1+ (0.01,0) [0|2.55] "s"  IMM
 SG_ M2I_Byrack_SysABStTm_IMM2_21 : 40|16@1+ (0.01,0) [0|655.35] "s"  IMM
 SG_ Reserved_21 : 56|8@1+ (1,0) [0|255] ""  IMM

BO_ 2332107430 M2I_Byrack_SUMDATA2__22: 8 MBMU
 SG_ CRC_M2I_Byrack_IMM2_22 : 0|8@1+ (1,0) [0|255] ""  IMM
 SG_ M2I_Byrack_HVS_IMM2_22 : 8|16@1+ (0.1,0) [0|6553.5] "v"  IMM
 SG_ M2I_Byrack_Enable_IMM2_22 : 24|2@1+ (1,0) [0|3] ""  IMM
 SG_ M2I_Byrack_ReVeEnable_IMM2_22 : 26|2@1+ (1,0) [0|3] ""  IMM
 SG_ Reserved_22 : 28|4@1+ (1,0) [0|15] ""  IMM
 SG_ M2I_Byrack_IsPostTm_IMM2_22 : 32|8@1+ (0.01,0) [0|2.55] "s"  IMM
 SG_ M2I_Byrack_SysABStTm_IMM2_22 : 40|16@1+ (0.01,0) [0|655.35] "s"  IMM
 SG_ Reserved_22 : 56|8@1+ (1,0) [0|255] ""  IMM

BO_ 2332107431 M2I_Byrack_SUMDATA2__23: 8 MBMU
 SG_ CRC_M2I_Byrack_IMM2_23 : 0|8@1+ (1,0) [0|255] ""  IMM
 SG_ M2I_Byrack_HVS_IMM2_23 : 8|16@1+ (0.1,0) [0|6553.5] "v"  IMM
 SG_ M2I_Byrack_Enable_IMM2_23 : 24|2@1+ (1,0) [0|3] ""  IMM
 SG_ M2I_Byrack_ReVeEnable_IMM2_23 : 26|2@1+ (1,0) [0|3] ""  IMM
 SG_ Reserved_23 : 28|4@1+ (1,0) [0|15] ""  IMM
 SG_ M2I_Byrack_IsPostTm_IMM2_23 : 32|8@1+ (0.01,0) [0|2.55] "s"  IMM
 SG_ M2I_Byrack_SysABStTm_IMM2_23 : 40|16@1+ (0.01,0) [0|655.35] "s"  IMM
 SG_ Reserved_23 : 56|8@1+ (1,0) [0|255] ""  IMM

BO_ 2332107432 M2I_Byrack_SUMDATA2__24: 8 MBMU
 SG_ CRC_M2I_Byrack_IMM2_24 : 0|8@1+ (1,0) [0|255] ""  IMM
 SG_ M2I_Byrack_HVS_IMM2_24 : 8|16@1+ (0.1,0) [0|6553.5] "v"  IMM
 SG_ M2I_Byrack_Enable_IMM2_24 : 24|2@1+ (1,0) [0|3] ""  IMM
 SG_ M2I_Byrack_ReVeEnable_IMM2_24 : 26|2@1+ (1,0) [0|3] ""  IMM
 SG_ Reserved_24 : 28|4@1+ (1,0) [0|15] ""  IMM
 SG_ M2I_Byrack_IsPostTm_IMM2_24 : 32|8@1+ (0.01,0) [0|2.55] "s"  IMM
 SG_ M2I_Byrack_SysABStTm_IMM2_24 : 40|16@1+ (0.01,0) [0|655.35] "s"  IMM
 SG_ Reserved_24 : 56|8@1+ (1,0) [0|255] ""  IMM

BO_ 2332107433 M2I_Byrack_SUMDATA2__25: 8 MBMU
 SG_ CRC_M2I_Byrack_IMM2_25 : 0|8@1+ (1,0) [0|255] ""  IMM
 SG_ M2I_Byrack_HVS_IMM2_25 : 8|16@1+ (0.1,0) [0|6553.5] "v"  IMM
 SG_ M2I_Byrack_Enable_IMM2_25 : 24|2@1+ (1,0) [0|3] ""  IMM
 SG_ M2I_Byrack_ReVeEnable_IMM2_25 : 26|2@1+ (1,0) [0|3] ""  IMM
 SG_ Reserved_25 : 28|4@1+ (1,0) [0|15] ""  IMM
 SG_ M2I_Byrack_IsPostTm_IMM2_25 : 32|8@1+ (0.01,0) [0|2.55] "s"  IMM
 SG_ M2I_Byrack_SysABStTm_IMM2_25 : 40|16@1+ (0.01,0) [0|655.35] "s"  IMM
 SG_ Reserved_25 : 56|8@1+ (1,0) [0|255] ""  IMM

BO_ 2332107434 M2I_Byrack_SUMDATA2__26: 8 MBMU
 SG_ CRC_M2I_Byrack_IMM2_26 : 0|8@1+ (1,0) [0|255] ""  IMM
 SG_ M2I_Byrack_HVS_IMM2_26 : 8|16@1+ (0.1,0) [0|6553.5] "v"  IMM
 SG_ M2I_Byrack_Enable_IMM2_26 : 24|2@1+ (1,0) [0|3] ""  IMM
 SG_ M2I_Byrack_ReVeEnable_IMM2_26 : 26|2@1+ (1,0) [0|3] ""  IMM
 SG_ Reserved_26 : 28|4@1+ (1,0) [0|15] ""  IMM
 SG_ M2I_Byrack_IsPostTm_IMM2_26 : 32|8@1+ (0.01,0) [0|2.55] "s"  IMM
 SG_ M2I_Byrack_SysABStTm_IMM2_26 : 40|16@1+ (0.01,0) [0|655.35] "s"  IMM
 SG_ Reserved_26 : 56|8@1+ (1,0) [0|255] ""  IMM

BO_ 2332107435 M2I_Byrack_SUMDATA2__27: 8 MBMU
 SG_ CRC_M2I_Byrack_IMM2_27 : 0|8@1+ (1,0) [0|255] ""  IMM
 SG_ M2I_Byrack_HVS_IMM2_27 : 8|16@1+ (0.1,0) [0|6553.5] "v"  IMM
 SG_ M2I_Byrack_Enable_IMM2_27 : 24|2@1+ (1,0) [0|3] ""  IMM
 SG_ M2I_Byrack_ReVeEnable_IMM2_27 : 26|2@1+ (1,0) [0|3] ""  IMM
 SG_ Reserved_27 : 28|4@1+ (1,0) [0|15] ""  IMM
 SG_ M2I_Byrack_IsPostTm_IMM2_27 : 32|8@1+ (0.01,0) [0|2.55] "s"  IMM
 SG_ M2I_Byrack_SysABStTm_IMM2_27 : 40|16@1+ (0.01,0) [0|655.35] "s"  IMM
 SG_ Reserved_27 : 56|8@1+ (1,0) [0|255] ""  IMM

BO_ 2332107436 M2I_Byrack_SUMDATA2__28: 8 MBMU
 SG_ CRC_M2I_Byrack_IMM2_28 : 0|8@1+ (1,0) [0|255] ""  IMM
 SG_ M2I_Byrack_HVS_IMM2_28 : 8|16@1+ (0.1,0) [0|6553.5] "v"  IMM
 SG_ M2I_Byrack_Enable_IMM2_28 : 24|2@1+ (1,0) [0|3] ""  IMM
 SG_ M2I_Byrack_ReVeEnable_IMM2_28 : 26|2@1+ (1,0) [0|3] ""  IMM
 SG_ Reserved_28 : 28|4@1+ (1,0) [0|15] ""  IMM
 SG_ M2I_Byrack_IsPostTm_IMM2_28 : 32|8@1+ (0.01,0) [0|2.55] "s"  IMM
 SG_ M2I_Byrack_SysABStTm_IMM2_28 : 40|16@1+ (0.01,0) [0|655.35] "s"  IMM
 SG_ Reserved_28 : 56|8@1+ (1,0) [0|255] ""  IMM

BO_ 2332107437 M2I_Byrack_SUMDATA2__29: 8 MBMU
 SG_ CRC_M2I_Byrack_IMM2_29 : 0|8@1+ (1,0) [0|255] ""  IMM
 SG_ M2I_Byrack_HVS_IMM2_29 : 8|16@1+ (0.1,0) [0|6553.5] "v"  IMM
 SG_ M2I_Byrack_Enable_IMM2_29 : 24|2@1+ (1,0) [0|3] ""  IMM
 SG_ M2I_Byrack_ReVeEnable_IMM2_29 : 26|2@1+ (1,0) [0|3] ""  IMM
 SG_ Reserved_29 : 28|4@1+ (1,0) [0|15] ""  IMM
 SG_ M2I_Byrack_IsPostTm_IMM2_29 : 32|8@1+ (0.01,0) [0|2.55] "s"  IMM
 SG_ M2I_Byrack_SysABStTm_IMM2_29 : 40|16@1+ (0.01,0) [0|655.35] "s"  IMM
 SG_ Reserved_29 : 56|8@1+ (1,0) [0|255] ""  IMM

BO_ 2332107438 M2I_Byrack_SUMDATA2__30: 8 MBMU
 SG_ CRC_M2I_Byrack_IMM2_30 : 0|8@1+ (1,0) [0|255] ""  IMM
 SG_ M2I_Byrack_HVS_IMM2_30 : 8|16@1+ (0.1,0) [0|6553.5] "v"  IMM
 SG_ M2I_Byrack_Enable_IMM2_30 : 24|2@1+ (1,0) [0|3] ""  IMM
 SG_ M2I_Byrack_ReVeEnable_IMM2_30 : 26|2@1+ (1,0) [0|3] ""  IMM
 SG_ Reserved_30 : 28|4@1+ (1,0) [0|15] ""  IMM
 SG_ M2I_Byrack_IsPostTm_IMM2_30 : 32|8@1+ (0.01,0) [0|2.55] "s"  IMM
 SG_ M2I_Byrack_SysABStTm_IMM2_30 : 40|16@1+ (0.01,0) [0|655.35] "s"  IMM
 SG_ Reserved_30 : 56|8@1+ (1,0) [0|255] ""  IMM

BO_ 2332107439 M2I_Byrack_SUMDATA2__31: 8 MBMU
 SG_ CRC_M2I_Byrack_IMM2_31 : 0|8@1+ (1,0) [0|255] ""  IMM
 SG_ M2I_Byrack_HVS_IMM2_31 : 8|16@1+ (0.1,0) [0|6553.5] "v"  IMM
 SG_ M2I_Byrack_Enable_IMM2_31 : 24|2@1+ (1,0) [0|3] ""  IMM
 SG_ M2I_Byrack_ReVeEnable_IMM2_31 : 26|2@1+ (1,0) [0|3] ""  IMM
 SG_ Reserved_31 : 28|4@1+ (1,0) [0|15] ""  IMM
 SG_ M2I_Byrack_IsPostTm_IMM2_31 : 32|8@1+ (0.01,0) [0|2.55] "s"  IMM
 SG_ M2I_Byrack_SysABStTm_IMM2_31 : 40|16@1+ (0.01,0) [0|655.35] "s"  IMM
 SG_ Reserved_31 : 56|8@1+ (1,0) [0|255] ""  IMM

BO_ 2332107665 M2I_Byrack_SUMDATA3__01: 8 MBMU
 SG_ CRC_M2I_Byrack_IMM3_01 : 0|8@1+ (1,0) [0|255] ""  IMM
 SG_ M2I_Byrack_HVS_IMM3_01 : 8|16@1+ (0.1,0) [0|6553.5] "v"  IMM
 SG_ M2I_Byrack_Enable_IMM3_01 : 24|2@1+ (1,0) [0|3] ""  IMM
 SG_ M2I_Byrack_ReVeEnable_IMM3_01 : 26|2@1+ (1,0) [0|3] ""  IMM
 SG_ Reserved_01 : 28|4@1+ (1,0) [0|15] ""  IMM
 SG_ M2I_Byrack_IsPostTm_IMM3_01 : 32|8@1+ (0.01,0) [0|2.55] "s"  IMM
 SG_ M2I_Byrack_SysABStTm_IMM3_01 : 40|16@1+ (0.01,0) [0|655.35] "s"  IMM
 SG_ Reserved_01 : 56|8@1+ (1,0) [0|255] ""  IMM

BO_ 2332107666 M2I_Byrack_SUMDATA3__02: 8 MBMU
 SG_ CRC_M2I_Byrack_IMM3_02 : 0|8@1+ (1,0) [0|255] ""  IMM
 SG_ M2I_Byrack_HVS_IMM3_02 : 8|16@1+ (0.1,0) [0|6553.5] "v"  IMM
 SG_ M2I_Byrack_Enable_IMM3_02 : 24|2@1+ (1,0) [0|3] ""  IMM
 SG_ M2I_Byrack_ReVeEnable_IMM3_02 : 26|2@1+ (1,0) [0|3] ""  IMM
 SG_ Reserved_02 : 28|4@1+ (1,0) [0|15] ""  IMM
 SG_ M2I_Byrack_IsPostTm_IMM3_02 : 32|8@1+ (0.01,0) [0|2.55] "s"  IMM
 SG_ M2I_Byrack_SysABStTm_IMM3_02 : 40|16@1+ (0.01,0) [0|655.35] "s"  IMM
 SG_ Reserved_02 : 56|8@1+ (1,0) [0|255] ""  IMM

BO_ 2332107667 M2I_Byrack_SUMDATA3__03: 8 MBMU
 SG_ CRC_M2I_Byrack_IMM3_03 : 0|8@1+ (1,0) [0|255] ""  IMM
 SG_ M2I_Byrack_HVS_IMM3_03 : 8|16@1+ (0.1,0) [0|6553.5] "v"  IMM
 SG_ M2I_Byrack_Enable_IMM3_03 : 24|2@1+ (1,0) [0|3] ""  IMM
 SG_ M2I_Byrack_ReVeEnable_IMM3_03 : 26|2@1+ (1,0) [0|3] ""  IMM
 SG_ Reserved_03 : 28|4@1+ (1,0) [0|15] ""  IMM
 SG_ M2I_Byrack_IsPostTm_IMM3_03 : 32|8@1+ (0.01,0) [0|2.55] "s"  IMM
 SG_ M2I_Byrack_SysABStTm_IMM3_03 : 40|16@1+ (0.01,0) [0|655.35] "s"  IMM
 SG_ Reserved_03 : 56|8@1+ (1,0) [0|255] ""  IMM

BO_ 2332107668 M2I_Byrack_SUMDATA3__04: 8 MBMU
 SG_ CRC_M2I_Byrack_IMM3_04 : 0|8@1+ (1,0) [0|255] ""  IMM
 SG_ M2I_Byrack_HVS_IMM3_04 : 8|16@1+ (0.1,0) [0|6553.5] "v"  IMM
 SG_ M2I_Byrack_Enable_IMM3_04 : 24|2@1+ (1,0) [0|3] ""  IMM
 SG_ M2I_Byrack_ReVeEnable_IMM3_04 : 26|2@1+ (1,0) [0|3] ""  IMM
 SG_ Reserved_04 : 28|4@1+ (1,0) [0|15] ""  IMM
 SG_ M2I_Byrack_IsPostTm_IMM3_04 : 32|8@1+ (0.01,0) [0|2.55] "s"  IMM
 SG_ M2I_Byrack_SysABStTm_IMM3_04 : 40|16@1+ (0.01,0) [0|655.35] "s"  IMM
 SG_ Reserved_04 : 56|8@1+ (1,0) [0|255] ""  IMM

BO_ 2332107669 M2I_Byrack_SUMDATA3__05: 8 MBMU
 SG_ CRC_M2I_Byrack_IMM3_05 : 0|8@1+ (1,0) [0|255] ""  IMM
 SG_ M2I_Byrack_HVS_IMM3_05 : 8|16@1+ (0.1,0) [0|6553.5] "v"  IMM
 SG_ M2I_Byrack_Enable_IMM3_05 : 24|2@1+ (1,0) [0|3] ""  IMM
 SG_ M2I_Byrack_ReVeEnable_IMM3_05 : 26|2@1+ (1,0) [0|3] ""  IMM
 SG_ Reserved_05 : 28|4@1+ (1,0) [0|15] ""  IMM
 SG_ M2I_Byrack_IsPostTm_IMM3_05 : 32|8@1+ (0.01,0) [0|2.55] "s"  IMM
 SG_ M2I_Byrack_SysABStTm_IMM3_05 : 40|16@1+ (0.01,0) [0|655.35] "s"  IMM
 SG_ Reserved_05 : 56|8@1+ (1,0) [0|255] ""  IMM

BO_ 2332107670 M2I_Byrack_SUMDATA3__06: 8 MBMU
 SG_ CRC_M2I_Byrack_IMM3_06 : 0|8@1+ (1,0) [0|255] ""  IMM
 SG_ M2I_Byrack_HVS_IMM3_06 : 8|16@1+ (0.1,0) [0|6553.5] "v"  IMM
 SG_ M2I_Byrack_Enable_IMM3_06 : 24|2@1+ (1,0) [0|3] ""  IMM
 SG_ M2I_Byrack_ReVeEnable_IMM3_06 : 26|2@1+ (1,0) [0|3] ""  IMM
 SG_ Reserved_06 : 28|4@1+ (1,0) [0|15] ""  IMM
 SG_ M2I_Byrack_IsPostTm_IMM3_06 : 32|8@1+ (0.01,0) [0|2.55] "s"  IMM
 SG_ M2I_Byrack_SysABStTm_IMM3_06 : 40|16@1+ (0.01,0) [0|655.35] "s"  IMM
 SG_ Reserved_06 : 56|8@1+ (1,0) [0|255] ""  IMM

BO_ 2332107671 M2I_Byrack_SUMDATA3__07: 8 MBMU
 SG_ CRC_M2I_Byrack_IMM3_07 : 0|8@1+ (1,0) [0|255] ""  IMM
 SG_ M2I_Byrack_HVS_IMM3_07 : 8|16@1+ (0.1,0) [0|6553.5] "v"  IMM
 SG_ M2I_Byrack_Enable_IMM3_07 : 24|2@1+ (1,0) [0|3] ""  IMM
 SG_ M2I_Byrack_ReVeEnable_IMM3_07 : 26|2@1+ (1,0) [0|3] ""  IMM
 SG_ Reserved_07 : 28|4@1+ (1,0) [0|15] ""  IMM
 SG_ M2I_Byrack_IsPostTm_IMM3_07 : 32|8@1+ (0.01,0) [0|2.55] "s"  IMM
 SG_ M2I_Byrack_SysABStTm_IMM3_07 : 40|16@1+ (0.01,0) [0|655.35] "s"  IMM
 SG_ Reserved_07 : 56|8@1+ (1,0) [0|255] ""  IMM

BO_ 2332107672 M2I_Byrack_SUMDATA3__08: 8 MBMU
 SG_ CRC_M2I_Byrack_IMM3_08 : 0|8@1+ (1,0) [0|255] ""  IMM
 SG_ M2I_Byrack_HVS_IMM3_08 : 8|16@1+ (0.1,0) [0|6553.5] "v"  IMM
 SG_ M2I_Byrack_Enable_IMM3_08 : 24|2@1+ (1,0) [0|3] ""  IMM
 SG_ M2I_Byrack_ReVeEnable_IMM3_08 : 26|2@1+ (1,0) [0|3] ""  IMM
 SG_ Reserved_08 : 28|4@1+ (1,0) [0|15] ""  IMM
 SG_ M2I_Byrack_IsPostTm_IMM3_08 : 32|8@1+ (0.01,0) [0|2.55] "s"  IMM
 SG_ M2I_Byrack_SysABStTm_IMM3_08 : 40|16@1+ (0.01,0) [0|655.35] "s"  IMM
 SG_ Reserved_08 : 56|8@1+ (1,0) [0|255] ""  IMM

BO_ 2332107673 M2I_Byrack_SUMDATA3__09: 8 MBMU
 SG_ CRC_M2I_Byrack_IMM3_09 : 0|8@1+ (1,0) [0|255] ""  IMM
 SG_ M2I_Byrack_HVS_IMM3_09 : 8|16@1+ (0.1,0) [0|6553.5] "v"  IMM
 SG_ M2I_Byrack_Enable_IMM3_09 : 24|2@1+ (1,0) [0|3] ""  IMM
 SG_ M2I_Byrack_ReVeEnable_IMM3_09 : 26|2@1+ (1,0) [0|3] ""  IMM
 SG_ Reserved_09 : 28|4@1+ (1,0) [0|15] ""  IMM
 SG_ M2I_Byrack_IsPostTm_IMM3_09 : 32|8@1+ (0.01,0) [0|2.55] "s"  IMM
 SG_ M2I_Byrack_SysABStTm_IMM3_09 : 40|16@1+ (0.01,0) [0|655.35] "s"  IMM
 SG_ Reserved_09 : 56|8@1+ (1,0) [0|255] ""  IMM

BO_ 2332107674 M2I_Byrack_SUMDATA3__10: 8 MBMU
 SG_ CRC_M2I_Byrack_IMM3_10 : 0|8@1+ (1,0) [0|255] ""  IMM
 SG_ M2I_Byrack_HVS_IMM3_10 : 8|16@1+ (0.1,0) [0|6553.5] "v"  IMM
 SG_ M2I_Byrack_Enable_IMM3_10 : 24|2@1+ (1,0) [0|3] ""  IMM
 SG_ M2I_Byrack_ReVeEnable_IMM3_10 : 26|2@1+ (1,0) [0|3] ""  IMM
 SG_ Reserved_10 : 28|4@1+ (1,0) [0|15] ""  IMM
 SG_ M2I_Byrack_IsPostTm_IMM3_10 : 32|8@1+ (0.01,0) [0|2.55] "s"  IMM
 SG_ M2I_Byrack_SysABStTm_IMM3_10 : 40|16@1+ (0.01,0) [0|655.35] "s"  IMM
 SG_ Reserved_10 : 56|8@1+ (1,0) [0|255] ""  IMM

BO_ 2332107675 M2I_Byrack_SUMDATA3__11: 8 MBMU
 SG_ CRC_M2I_Byrack_IMM3_11 : 0|8@1+ (1,0) [0|255] ""  IMM
 SG_ M2I_Byrack_HVS_IMM3_11 : 8|16@1+ (0.1,0) [0|6553.5] "v"  IMM
 SG_ M2I_Byrack_Enable_IMM3_11 : 24|2@1+ (1,0) [0|3] ""  IMM
 SG_ M2I_Byrack_ReVeEnable_IMM3_11 : 26|2@1+ (1,0) [0|3] ""  IMM
 SG_ Reserved_11 : 28|4@1+ (1,0) [0|15] ""  IMM
 SG_ M2I_Byrack_IsPostTm_IMM3_11 : 32|8@1+ (0.01,0) [0|2.55] "s"  IMM
 SG_ M2I_Byrack_SysABStTm_IMM3_11 : 40|16@1+ (0.01,0) [0|655.35] "s"  IMM
 SG_ Reserved_11 : 56|8@1+ (1,0) [0|255] ""  IMM

BO_ 2332107676 M2I_Byrack_SUMDATA3__12: 8 MBMU
 SG_ CRC_M2I_Byrack_IMM3_12 : 0|8@1+ (1,0) [0|255] ""  IMM
 SG_ M2I_Byrack_HVS_IMM3_12 : 8|16@1+ (0.1,0) [0|6553.5] "v"  IMM
 SG_ M2I_Byrack_Enable_IMM3_12 : 24|2@1+ (1,0) [0|3] ""  IMM
 SG_ M2I_Byrack_ReVeEnable_IMM3_12 : 26|2@1+ (1,0) [0|3] ""  IMM
 SG_ Reserved_12 : 28|4@1+ (1,0) [0|15] ""  IMM
 SG_ M2I_Byrack_IsPostTm_IMM3_12 : 32|8@1+ (0.01,0) [0|2.55] "s"  IMM
 SG_ M2I_Byrack_SysABStTm_IMM3_12 : 40|16@1+ (0.01,0) [0|655.35] "s"  IMM
 SG_ Reserved_12 : 56|8@1+ (1,0) [0|255] ""  IMM

BO_ 2332107677 M2I_Byrack_SUMDATA3__13: 8 MBMU
 SG_ CRC_M2I_Byrack_IMM3_13 : 0|8@1+ (1,0) [0|255] ""  IMM
 SG_ M2I_Byrack_HVS_IMM3_13 : 8|16@1+ (0.1,0) [0|6553.5] "v"  IMM
 SG_ M2I_Byrack_Enable_IMM3_13 : 24|2@1+ (1,0) [0|3] ""  IMM
 SG_ M2I_Byrack_ReVeEnable_IMM3_13 : 26|2@1+ (1,0) [0|3] ""  IMM
 SG_ Reserved_13 : 28|4@1+ (1,0) [0|15] ""  IMM
 SG_ M2I_Byrack_IsPostTm_IMM3_13 : 32|8@1+ (0.01,0) [0|2.55] "s"  IMM
 SG_ M2I_Byrack_SysABStTm_IMM3_13 : 40|16@1+ (0.01,0) [0|655.35] "s"  IMM
 SG_ Reserved_13 : 56|8@1+ (1,0) [0|255] ""  IMM

BO_ 2332107678 M2I_Byrack_SUMDATA3__14: 8 MBMU
 SG_ CRC_M2I_Byrack_IMM3_14 : 0|8@1+ (1,0) [0|255] ""  IMM
 SG_ M2I_Byrack_HVS_IMM3_14 : 8|16@1+ (0.1,0) [0|6553.5] "v"  IMM
 SG_ M2I_Byrack_Enable_IMM3_14 : 24|2@1+ (1,0) [0|3] ""  IMM
 SG_ M2I_Byrack_ReVeEnable_IMM3_14 : 26|2@1+ (1,0) [0|3] ""  IMM
 SG_ Reserved_14 : 28|4@1+ (1,0) [0|15] ""  IMM
 SG_ M2I_Byrack_IsPostTm_IMM3_14 : 32|8@1+ (0.01,0) [0|2.55] "s"  IMM
 SG_ M2I_Byrack_SysABStTm_IMM3_14 : 40|16@1+ (0.01,0) [0|655.35] "s"  IMM
 SG_ Reserved_14 : 56|8@1+ (1,0) [0|255] ""  IMM

BO_ 2332107679 M2I_Byrack_SUMDATA3__15: 8 MBMU
 SG_ CRC_M2I_Byrack_IMM3_15 : 0|8@1+ (1,0) [0|255] ""  IMM
 SG_ M2I_Byrack_HVS_IMM3_15 : 8|16@1+ (0.1,0) [0|6553.5] "v"  IMM
 SG_ M2I_Byrack_Enable_IMM3_15 : 24|2@1+ (1,0) [0|3] ""  IMM
 SG_ M2I_Byrack_ReVeEnable_IMM3_15 : 26|2@1+ (1,0) [0|3] ""  IMM
 SG_ Reserved_15 : 28|4@1+ (1,0) [0|15] ""  IMM
 SG_ M2I_Byrack_IsPostTm_IMM3_15 : 32|8@1+ (0.01,0) [0|2.55] "s"  IMM
 SG_ M2I_Byrack_SysABStTm_IMM3_15 : 40|16@1+ (0.01,0) [0|655.35] "s"  IMM
 SG_ Reserved_15 : 56|8@1+ (1,0) [0|255] ""  IMM

BO_ 2332107680 M2I_Byrack_SUMDATA3__16: 8 MBMU
 SG_ CRC_M2I_Byrack_IMM3_16 : 0|8@1+ (1,0) [0|255] ""  IMM
 SG_ M2I_Byrack_HVS_IMM3_16 : 8|16@1+ (0.1,0) [0|6553.5] "v"  IMM
 SG_ M2I_Byrack_Enable_IMM3_16 : 24|2@1+ (1,0) [0|3] ""  IMM
 SG_ M2I_Byrack_ReVeEnable_IMM3_16 : 26|2@1+ (1,0) [0|3] ""  IMM
 SG_ Reserved_16 : 28|4@1+ (1,0) [0|15] ""  IMM
 SG_ M2I_Byrack_IsPostTm_IMM3_16 : 32|8@1+ (0.01,0) [0|2.55] "s"  IMM
 SG_ M2I_Byrack_SysABStTm_IMM3_16 : 40|16@1+ (0.01,0) [0|655.35] "s"  IMM
 SG_ Reserved_16 : 56|8@1+ (1,0) [0|255] ""  IMM

BO_ 2332107681 M2I_Byrack_SUMDATA3__17: 8 MBMU
 SG_ CRC_M2I_Byrack_IMM3_17 : 0|8@1+ (1,0) [0|255] ""  IMM
 SG_ M2I_Byrack_HVS_IMM3_17 : 8|16@1+ (0.1,0) [0|6553.5] "v"  IMM
 SG_ M2I_Byrack_Enable_IMM3_17 : 24|2@1+ (1,0) [0|3] ""  IMM
 SG_ M2I_Byrack_ReVeEnable_IMM3_17 : 26|2@1+ (1,0) [0|3] ""  IMM
 SG_ Reserved_17 : 28|4@1+ (1,0) [0|15] ""  IMM
 SG_ M2I_Byrack_IsPostTm_IMM3_17 : 32|8@1+ (0.01,0) [0|2.55] "s"  IMM
 SG_ M2I_Byrack_SysABStTm_IMM3_17 : 40|16@1+ (0.01,0) [0|655.35] "s"  IMM
 SG_ Reserved_17 : 56|8@1+ (1,0) [0|255] ""  IMM

BO_ 2332107682 M2I_Byrack_SUMDATA3__18: 8 MBMU
 SG_ CRC_M2I_Byrack_IMM3_18 : 0|8@1+ (1,0) [0|255] ""  IMM
 SG_ M2I_Byrack_HVS_IMM3_18 : 8|16@1+ (0.1,0) [0|6553.5] "v"  IMM
 SG_ M2I_Byrack_Enable_IMM3_18 : 24|2@1+ (1,0) [0|3] ""  IMM
 SG_ M2I_Byrack_ReVeEnable_IMM3_18 : 26|2@1+ (1,0) [0|3] ""  IMM
 SG_ Reserved_18 : 28|4@1+ (1,0) [0|15] ""  IMM
 SG_ M2I_Byrack_IsPostTm_IMM3_18 : 32|8@1+ (0.01,0) [0|2.55] "s"  IMM
 SG_ M2I_Byrack_SysABStTm_IMM3_18 : 40|16@1+ (0.01,0) [0|655.35] "s"  IMM
 SG_ Reserved_18 : 56|8@1+ (1,0) [0|255] ""  IMM

BO_ 2332107683 M2I_Byrack_SUMDATA3__19: 8 MBMU
 SG_ CRC_M2I_Byrack_IMM3_19 : 0|8@1+ (1,0) [0|255] ""  IMM
 SG_ M2I_Byrack_HVS_IMM3_19 : 8|16@1+ (0.1,0) [0|6553.5] "v"  IMM
 SG_ M2I_Byrack_Enable_IMM3_19 : 24|2@1+ (1,0) [0|3] ""  IMM
 SG_ M2I_Byrack_ReVeEnable_IMM3_19 : 26|2@1+ (1,0) [0|3] ""  IMM
 SG_ Reserved_19 : 28|4@1+ (1,0) [0|15] ""  IMM
 SG_ M2I_Byrack_IsPostTm_IMM3_19 : 32|8@1+ (0.01,0) [0|2.55] "s"  IMM
 SG_ M2I_Byrack_SysABStTm_IMM3_19 : 40|16@1+ (0.01,0) [0|655.35] "s"  IMM
 SG_ Reserved_19 : 56|8@1+ (1,0) [0|255] ""  IMM

BO_ 2332107684 M2I_Byrack_SUMDATA3__20: 8 MBMU
 SG_ CRC_M2I_Byrack_IMM3_20 : 0|8@1+ (1,0) [0|255] ""  IMM
 SG_ M2I_Byrack_HVS_IMM3_20 : 8|16@1+ (0.1,0) [0|6553.5] "v"  IMM
 SG_ M2I_Byrack_Enable_IMM3_20 : 24|2@1+ (1,0) [0|3] ""  IMM
 SG_ M2I_Byrack_ReVeEnable_IMM3_20 : 26|2@1+ (1,0) [0|3] ""  IMM
 SG_ Reserved_20 : 28|4@1+ (1,0) [0|15] ""  IMM
 SG_ M2I_Byrack_IsPostTm_IMM3_20 : 32|8@1+ (0.01,0) [0|2.55] "s"  IMM
 SG_ M2I_Byrack_SysABStTm_IMM3_20 : 40|16@1+ (0.01,0) [0|655.35] "s"  IMM
 SG_ Reserved_20 : 56|8@1+ (1,0) [0|255] ""  IMM

BO_ 2332107685 M2I_Byrack_SUMDATA3__21: 8 MBMU
 SG_ CRC_M2I_Byrack_IMM3_21 : 0|8@1+ (1,0) [0|255] ""  IMM
 SG_ M2I_Byrack_HVS_IMM3_21 : 8|16@1+ (0.1,0) [0|6553.5] "v"  IMM
 SG_ M2I_Byrack_Enable_IMM3_21 : 24|2@1+ (1,0) [0|3] ""  IMM
 SG_ M2I_Byrack_ReVeEnable_IMM3_21 : 26|2@1+ (1,0) [0|3] ""  IMM
 SG_ Reserved_21 : 28|4@1+ (1,0) [0|15] ""  IMM
 SG_ M2I_Byrack_IsPostTm_IMM3_21 : 32|8@1+ (0.01,0) [0|2.55] "s"  IMM
 SG_ M2I_Byrack_SysABStTm_IMM3_21 : 40|16@1+ (0.01,0) [0|655.35] "s"  IMM
 SG_ Reserved_21 : 56|8@1+ (1,0) [0|255] ""  IMM

BO_ 2332107686 M2I_Byrack_SUMDATA3__22: 8 MBMU
 SG_ CRC_M2I_Byrack_IMM3_22 : 0|8@1+ (1,0) [0|255] ""  IMM
 SG_ M2I_Byrack_HVS_IMM3_22 : 8|16@1+ (0.1,0) [0|6553.5] "v"  IMM
 SG_ M2I_Byrack_Enable_IMM3_22 : 24|2@1+ (1,0) [0|3] ""  IMM
 SG_ M2I_Byrack_ReVeEnable_IMM3_22 : 26|2@1+ (1,0) [0|3] ""  IMM
 SG_ Reserved_22 : 28|4@1+ (1,0) [0|15] ""  IMM
 SG_ M2I_Byrack_IsPostTm_IMM3_22 : 32|8@1+ (0.01,0) [0|2.55] "s"  IMM
 SG_ M2I_Byrack_SysABStTm_IMM3_22 : 40|16@1+ (0.01,0) [0|655.35] "s"  IMM
 SG_ Reserved_22 : 56|8@1+ (1,0) [0|255] ""  IMM

BO_ 2332107687 M2I_Byrack_SUMDATA3__23: 8 MBMU
 SG_ CRC_M2I_Byrack_IMM3_23 : 0|8@1+ (1,0) [0|255] ""  IMM
 SG_ M2I_Byrack_HVS_IMM3_23 : 8|16@1+ (0.1,0) [0|6553.5] "v"  IMM
 SG_ M2I_Byrack_Enable_IMM3_23 : 24|2@1+ (1,0) [0|3] ""  IMM
 SG_ M2I_Byrack_ReVeEnable_IMM3_23 : 26|2@1+ (1,0) [0|3] ""  IMM
 SG_ Reserved_23 : 28|4@1+ (1,0) [0|15] ""  IMM
 SG_ M2I_Byrack_IsPostTm_IMM3_23 : 32|8@1+ (0.01,0) [0|2.55] "s"  IMM
 SG_ M2I_Byrack_SysABStTm_IMM3_23 : 40|16@1+ (0.01,0) [0|655.35] "s"  IMM
 SG_ Reserved_23 : 56|8@1+ (1,0) [0|255] ""  IMM

BO_ 2332107688 M2I_Byrack_SUMDATA3__24: 8 MBMU
 SG_ CRC_M2I_Byrack_IMM3_24 : 0|8@1+ (1,0) [0|255] ""  IMM
 SG_ M2I_Byrack_HVS_IMM3_24 : 8|16@1+ (0.1,0) [0|6553.5] "v"  IMM
 SG_ M2I_Byrack_Enable_IMM3_24 : 24|2@1+ (1,0) [0|3] ""  IMM
 SG_ M2I_Byrack_ReVeEnable_IMM3_24 : 26|2@1+ (1,0) [0|3] ""  IMM
 SG_ Reserved_24 : 28|4@1+ (1,0) [0|15] ""  IMM
 SG_ M2I_Byrack_IsPostTm_IMM3_24 : 32|8@1+ (0.01,0) [0|2.55] "s"  IMM
 SG_ M2I_Byrack_SysABStTm_IMM3_24 : 40|16@1+ (0.01,0) [0|655.35] "s"  IMM
 SG_ Reserved_24 : 56|8@1+ (1,0) [0|255] ""  IMM

BO_ 2332107689 M2I_Byrack_SUMDATA3__25: 8 MBMU
 SG_ CRC_M2I_Byrack_IMM3_25 : 0|8@1+ (1,0) [0|255] ""  IMM
 SG_ M2I_Byrack_HVS_IMM3_25 : 8|16@1+ (0.1,0) [0|6553.5] "v"  IMM
 SG_ M2I_Byrack_Enable_IMM3_25 : 24|2@1+ (1,0) [0|3] ""  IMM
 SG_ M2I_Byrack_ReVeEnable_IMM3_25 : 26|2@1+ (1,0) [0|3] ""  IMM
 SG_ Reserved_25 : 28|4@1+ (1,0) [0|15] ""  IMM
 SG_ M2I_Byrack_IsPostTm_IMM3_25 : 32|8@1+ (0.01,0) [0|2.55] "s"  IMM
 SG_ M2I_Byrack_SysABStTm_IMM3_25 : 40|16@1+ (0.01,0) [0|655.35] "s"  IMM
 SG_ Reserved_25 : 56|8@1+ (1,0) [0|255] ""  IMM

BO_ 2332107690 M2I_Byrack_SUMDATA3__26: 8 MBMU
 SG_ CRC_M2I_Byrack_IMM3_26 : 0|8@1+ (1,0) [0|255] ""  IMM
 SG_ M2I_Byrack_HVS_IMM3_26 : 8|16@1+ (0.1,0) [0|6553.5] "v"  IMM
 SG_ M2I_Byrack_Enable_IMM3_26 : 24|2@1+ (1,0) [0|3] ""  IMM
 SG_ M2I_Byrack_ReVeEnable_IMM3_26 : 26|2@1+ (1,0) [0|3] ""  IMM
 SG_ Reserved_26 : 28|4@1+ (1,0) [0|15] ""  IMM
 SG_ M2I_Byrack_IsPostTm_IMM3_26 : 32|8@1+ (0.01,0) [0|2.55] "s"  IMM
 SG_ M2I_Byrack_SysABStTm_IMM3_26 : 40|16@1+ (0.01,0) [0|655.35] "s"  IMM
 SG_ Reserved_26 : 56|8@1+ (1,0) [0|255] ""  IMM

BO_ 2332107691 M2I_Byrack_SUMDATA3__27: 8 MBMU
 SG_ CRC_M2I_Byrack_IMM3_27 : 0|8@1+ (1,0) [0|255] ""  IMM
 SG_ M2I_Byrack_HVS_IMM3_27 : 8|16@1+ (0.1,0) [0|6553.5] "v"  IMM
 SG_ M2I_Byrack_Enable_IMM3_27 : 24|2@1+ (1,0) [0|3] ""  IMM
 SG_ M2I_Byrack_ReVeEnable_IMM3_27 : 26|2@1+ (1,0) [0|3] ""  IMM
 SG_ Reserved_27 : 28|4@1+ (1,0) [0|15] ""  IMM
 SG_ M2I_Byrack_IsPostTm_IMM3_27 : 32|8@1+ (0.01,0) [0|2.55] "s"  IMM
 SG_ M2I_Byrack_SysABStTm_IMM3_27 : 40|16@1+ (0.01,0) [0|655.35] "s"  IMM
 SG_ Reserved_27 : 56|8@1+ (1,0) [0|255] ""  IMM

BO_ 2332107692 M2I_Byrack_SUMDATA3__28: 8 MBMU
 SG_ CRC_M2I_Byrack_IMM3_28 : 0|8@1+ (1,0) [0|255] ""  IMM
 SG_ M2I_Byrack_HVS_IMM3_28 : 8|16@1+ (0.1,0) [0|6553.5] "v"  IMM
 SG_ M2I_Byrack_Enable_IMM3_28 : 24|2@1+ (1,0) [0|3] ""  IMM
 SG_ M2I_Byrack_ReVeEnable_IMM3_28 : 26|2@1+ (1,0) [0|3] ""  IMM
 SG_ Reserved_28 : 28|4@1+ (1,0) [0|15] ""  IMM
 SG_ M2I_Byrack_IsPostTm_IMM3_28 : 32|8@1+ (0.01,0) [0|2.55] "s"  IMM
 SG_ M2I_Byrack_SysABStTm_IMM3_28 : 40|16@1+ (0.01,0) [0|655.35] "s"  IMM
 SG_ Reserved_28 : 56|8@1+ (1,0) [0|255] ""  IMM

BO_ 2332107693 M2I_Byrack_SUMDATA3__29: 8 MBMU
 SG_ CRC_M2I_Byrack_IMM3_29 : 0|8@1+ (1,0) [0|255] ""  IMM
 SG_ M2I_Byrack_HVS_IMM3_29 : 8|16@1+ (0.1,0) [0|6553.5] "v"  IMM
 SG_ M2I_Byrack_Enable_IMM3_29 : 24|2@1+ (1,0) [0|3] ""  IMM
 SG_ M2I_Byrack_ReVeEnable_IMM3_29 : 26|2@1+ (1,0) [0|3] ""  IMM
 SG_ Reserved_29 : 28|4@1+ (1,0) [0|15] ""  IMM
 SG_ M2I_Byrack_IsPostTm_IMM3_29 : 32|8@1+ (0.01,0) [0|2.55] "s"  IMM
 SG_ M2I_Byrack_SysABStTm_IMM3_29 : 40|16@1+ (0.01,0) [0|655.35] "s"  IMM
 SG_ Reserved_29 : 56|8@1+ (1,0) [0|255] ""  IMM

BO_ 2332107694 M2I_Byrack_SUMDATA3__30: 8 MBMU
 SG_ CRC_M2I_Byrack_IMM3_30 : 0|8@1+ (1,0) [0|255] ""  IMM
 SG_ M2I_Byrack_HVS_IMM3_30 : 8|16@1+ (0.1,0) [0|6553.5] "v"  IMM
 SG_ M2I_Byrack_Enable_IMM3_30 : 24|2@1+ (1,0) [0|3] ""  IMM
 SG_ M2I_Byrack_ReVeEnable_IMM3_30 : 26|2@1+ (1,0) [0|3] ""  IMM
 SG_ Reserved_30 : 28|4@1+ (1,0) [0|15] ""  IMM
 SG_ M2I_Byrack_IsPostTm_IMM3_30 : 32|8@1+ (0.01,0) [0|2.55] "s"  IMM
 SG_ M2I_Byrack_SysABStTm_IMM3_30 : 40|16@1+ (0.01,0) [0|655.35] "s"  IMM
 SG_ Reserved_30 : 56|8@1+ (1,0) [0|255] ""  IMM

BO_ 2332107695 M2I_Byrack_SUMDATA3__31: 8 MBMU
 SG_ CRC_M2I_Byrack_IMM3_31 : 0|8@1+ (1,0) [0|255] ""  IMM
 SG_ M2I_Byrack_HVS_IMM3_31 : 8|16@1+ (0.1,0) [0|6553.5] "v"  IMM
 SG_ M2I_Byrack_Enable_IMM3_31 : 24|2@1+ (1,0) [0|3] ""  IMM
 SG_ M2I_Byrack_ReVeEnable_IMM3_31 : 26|2@1+ (1,0) [0|3] ""  IMM
 SG_ Reserved_31 : 28|4@1+ (1,0) [0|15] ""  IMM
 SG_ M2I_Byrack_IsPostTm_IMM3_31 : 32|8@1+ (0.01,0) [0|2.55] "s"  IMM
 SG_ M2I_Byrack_SysABStTm_IMM3_31 : 40|16@1+ (0.01,0) [0|655.35] "s"  IMM
 SG_ Reserved_31 : 56|8@1+ (1,0) [0|255] ""  IMM

BO_ 2332107921 M2I_Byrack_SUMDATA4__01: 8 MBMU
 SG_ CRC_M2I_Byrack_IMM4_01 : 0|8@1+ (1,0) [0|255] ""  IMM
 SG_ M2I_Byrack_HVS_IMM4_01 : 8|16@1+ (0.1,0) [0|6553.5] "v"  IMM
 SG_ M2I_Byrack_Enable_IMM4_01 : 24|2@1+ (1,0) [0|3] ""  IMM
 SG_ M2I_Byrack_ReVeEnable_IMM4_01 : 26|2@1+ (1,0) [0|3] ""  IMM
 SG_ Reserved_01 : 28|4@1+ (1,0) [0|15] ""  IMM
 SG_ M2I_Byrack_IsPostTm_IMM4_01 : 32|8@1+ (0.01,0) [0|2.55] "s"  IMM
 SG_ M2I_Byrack_SysABStTm_IMM4_01 : 40|16@1+ (0.01,0) [0|655.35] "s"  IMM
 SG_ Reserved_01 : 56|8@1+ (1,0) [0|255] ""  IMM

BO_ 2332107922 M2I_Byrack_SUMDATA4__02: 8 MBMU
 SG_ CRC_M2I_Byrack_IMM4_02 : 0|8@1+ (1,0) [0|255] ""  IMM
 SG_ M2I_Byrack_HVS_IMM4_02 : 8|16@1+ (0.1,0) [0|6553.5] "v"  IMM
 SG_ M2I_Byrack_Enable_IMM4_02 : 24|2@1+ (1,0) [0|3] ""  IMM
 SG_ M2I_Byrack_ReVeEnable_IMM4_02 : 26|2@1+ (1,0) [0|3] ""  IMM
 SG_ Reserved_02 : 28|4@1+ (1,0) [0|15] ""  IMM
 SG_ M2I_Byrack_IsPostTm_IMM4_02 : 32|8@1+ (0.01,0) [0|2.55] "s"  IMM
 SG_ M2I_Byrack_SysABStTm_IMM4_02 : 40|16@1+ (0.01,0) [0|655.35] "s"  IMM
 SG_ Reserved_02 : 56|8@1+ (1,0) [0|255] ""  IMM

BO_ 2332107923 M2I_Byrack_SUMDATA4__03: 8 MBMU
 SG_ CRC_M2I_Byrack_IMM4_03 : 0|8@1+ (1,0) [0|255] ""  IMM
 SG_ M2I_Byrack_HVS_IMM4_03 : 8|16@1+ (0.1,0) [0|6553.5] "v"  IMM
 SG_ M2I_Byrack_Enable_IMM4_03 : 24|2@1+ (1,0) [0|3] ""  IMM
 SG_ M2I_Byrack_ReVeEnable_IMM4_03 : 26|2@1+ (1,0) [0|3] ""  IMM
 SG_ Reserved_03 : 28|4@1+ (1,0) [0|15] ""  IMM
 SG_ M2I_Byrack_IsPostTm_IMM4_03 : 32|8@1+ (0.01,0) [0|2.55] "s"  IMM
 SG_ M2I_Byrack_SysABStTm_IMM4_03 : 40|16@1+ (0.01,0) [0|655.35] "s"  IMM
 SG_ Reserved_03 : 56|8@1+ (1,0) [0|255] ""  IMM

BO_ 2332107924 M2I_Byrack_SUMDATA4__04: 8 MBMU
 SG_ CRC_M2I_Byrack_IMM4_04 : 0|8@1+ (1,0) [0|255] ""  IMM
 SG_ M2I_Byrack_HVS_IMM4_04 : 8|16@1+ (0.1,0) [0|6553.5] "v"  IMM
 SG_ M2I_Byrack_Enable_IMM4_04 : 24|2@1+ (1,0) [0|3] ""  IMM
 SG_ M2I_Byrack_ReVeEnable_IMM4_04 : 26|2@1+ (1,0) [0|3] ""  IMM
 SG_ Reserved_04 : 28|4@1+ (1,0) [0|15] ""  IMM
 SG_ M2I_Byrack_IsPostTm_IMM4_04 : 32|8@1+ (0.01,0) [0|2.55] "s"  IMM
 SG_ M2I_Byrack_SysABStTm_IMM4_04 : 40|16@1+ (0.01,0) [0|655.35] "s"  IMM
 SG_ Reserved_04 : 56|8@1+ (1,0) [0|255] ""  IMM

BO_ 2332107925 M2I_Byrack_SUMDATA4__05: 8 MBMU
 SG_ CRC_M2I_Byrack_IMM4_05 : 0|8@1+ (1,0) [0|255] ""  IMM
 SG_ M2I_Byrack_HVS_IMM4_05 : 8|16@1+ (0.1,0) [0|6553.5] "v"  IMM
 SG_ M2I_Byrack_Enable_IMM4_05 : 24|2@1+ (1,0) [0|3] ""  IMM
 SG_ M2I_Byrack_ReVeEnable_IMM4_05 : 26|2@1+ (1,0) [0|3] ""  IMM
 SG_ Reserved_05 : 28|4@1+ (1,0) [0|15] ""  IMM
 SG_ M2I_Byrack_IsPostTm_IMM4_05 : 32|8@1+ (0.01,0) [0|2.55] "s"  IMM
 SG_ M2I_Byrack_SysABStTm_IMM4_05 : 40|16@1+ (0.01,0) [0|655.35] "s"  IMM
 SG_ Reserved_05 : 56|8@1+ (1,0) [0|255] ""  IMM

BO_ 2332107926 M2I_Byrack_SUMDATA4__06: 8 MBMU
 SG_ CRC_M2I_Byrack_IMM4_06 : 0|8@1+ (1,0) [0|255] ""  IMM
 SG_ M2I_Byrack_HVS_IMM4_06 : 8|16@1+ (0.1,0) [0|6553.5] "v"  IMM
 SG_ M2I_Byrack_Enable_IMM4_06 : 24|2@1+ (1,0) [0|3] ""  IMM
 SG_ M2I_Byrack_ReVeEnable_IMM4_06 : 26|2@1+ (1,0) [0|3] ""  IMM
 SG_ Reserved_06 : 28|4@1+ (1,0) [0|15] ""  IMM
 SG_ M2I_Byrack_IsPostTm_IMM4_06 : 32|8@1+ (0.01,0) [0|2.55] "s"  IMM
 SG_ M2I_Byrack_SysABStTm_IMM4_06 : 40|16@1+ (0.01,0) [0|655.35] "s"  IMM
 SG_ Reserved_06 : 56|8@1+ (1,0) [0|255] ""  IMM

BO_ 2332107927 M2I_Byrack_SUMDATA4__07: 8 MBMU
 SG_ CRC_M2I_Byrack_IMM4_07 : 0|8@1+ (1,0) [0|255] ""  IMM
 SG_ M2I_Byrack_HVS_IMM4_07 : 8|16@1+ (0.1,0) [0|6553.5] "v"  IMM
 SG_ M2I_Byrack_Enable_IMM4_07 : 24|2@1+ (1,0) [0|3] ""  IMM
 SG_ M2I_Byrack_ReVeEnable_IMM4_07 : 26|2@1+ (1,0) [0|3] ""  IMM
 SG_ Reserved_07 : 28|4@1+ (1,0) [0|15] ""  IMM
 SG_ M2I_Byrack_IsPostTm_IMM4_07 : 32|8@1+ (0.01,0) [0|2.55] "s"  IMM
 SG_ M2I_Byrack_SysABStTm_IMM4_07 : 40|16@1+ (0.01,0) [0|655.35] "s"  IMM
 SG_ Reserved_07 : 56|8@1+ (1,0) [0|255] ""  IMM

BO_ 2332107928 M2I_Byrack_SUMDATA4__08: 8 MBMU
 SG_ CRC_M2I_Byrack_IMM4_08 : 0|8@1+ (1,0) [0|255] ""  IMM
 SG_ M2I_Byrack_HVS_IMM4_08 : 8|16@1+ (0.1,0) [0|6553.5] "v"  IMM
 SG_ M2I_Byrack_Enable_IMM4_08 : 24|2@1+ (1,0) [0|3] ""  IMM
 SG_ M2I_Byrack_ReVeEnable_IMM4_08 : 26|2@1+ (1,0) [0|3] ""  IMM
 SG_ Reserved_08 : 28|4@1+ (1,0) [0|15] ""  IMM
 SG_ M2I_Byrack_IsPostTm_IMM4_08 : 32|8@1+ (0.01,0) [0|2.55] "s"  IMM
 SG_ M2I_Byrack_SysABStTm_IMM4_08 : 40|16@1+ (0.01,0) [0|655.35] "s"  IMM
 SG_ Reserved_08 : 56|8@1+ (1,0) [0|255] ""  IMM

BO_ 2332107929 M2I_Byrack_SUMDATA4__09: 8 MBMU
 SG_ CRC_M2I_Byrack_IMM4_09 : 0|8@1+ (1,0) [0|255] ""  IMM
 SG_ M2I_Byrack_HVS_IMM4_09 : 8|16@1+ (0.1,0) [0|6553.5] "v"  IMM
 SG_ M2I_Byrack_Enable_IMM4_09 : 24|2@1+ (1,0) [0|3] ""  IMM
 SG_ M2I_Byrack_ReVeEnable_IMM4_09 : 26|2@1+ (1,0) [0|3] ""  IMM
 SG_ Reserved_09 : 28|4@1+ (1,0) [0|15] ""  IMM
 SG_ M2I_Byrack_IsPostTm_IMM4_09 : 32|8@1+ (0.01,0) [0|2.55] "s"  IMM
 SG_ M2I_Byrack_SysABStTm_IMM4_09 : 40|16@1+ (0.01,0) [0|655.35] "s"  IMM
 SG_ Reserved_09 : 56|8@1+ (1,0) [0|255] ""  IMM

BO_ 2332107930 M2I_Byrack_SUMDATA4__10: 8 MBMU
 SG_ CRC_M2I_Byrack_IMM4_10 : 0|8@1+ (1,0) [0|255] ""  IMM
 SG_ M2I_Byrack_HVS_IMM4_10 : 8|16@1+ (0.1,0) [0|6553.5] "v"  IMM
 SG_ M2I_Byrack_Enable_IMM4_10 : 24|2@1+ (1,0) [0|3] ""  IMM
 SG_ M2I_Byrack_ReVeEnable_IMM4_10 : 26|2@1+ (1,0) [0|3] ""  IMM
 SG_ Reserved_10 : 28|4@1+ (1,0) [0|15] ""  IMM
 SG_ M2I_Byrack_IsPostTm_IMM4_10 : 32|8@1+ (0.01,0) [0|2.55] "s"  IMM
 SG_ M2I_Byrack_SysABStTm_IMM4_10 : 40|16@1+ (0.01,0) [0|655.35] "s"  IMM
 SG_ Reserved_10 : 56|8@1+ (1,0) [0|255] ""  IMM

BO_ 2332107931 M2I_Byrack_SUMDATA4__11: 8 MBMU
 SG_ CRC_M2I_Byrack_IMM4_11 : 0|8@1+ (1,0) [0|255] ""  IMM
 SG_ M2I_Byrack_HVS_IMM4_11 : 8|16@1+ (0.1,0) [0|6553.5] "v"  IMM
 SG_ M2I_Byrack_Enable_IMM4_11 : 24|2@1+ (1,0) [0|3] ""  IMM
 SG_ M2I_Byrack_ReVeEnable_IMM4_11 : 26|2@1+ (1,0) [0|3] ""  IMM
 SG_ Reserved_11 : 28|4@1+ (1,0) [0|15] ""  IMM
 SG_ M2I_Byrack_IsPostTm_IMM4_11 : 32|8@1+ (0.01,0) [0|2.55] "s"  IMM
 SG_ M2I_Byrack_SysABStTm_IMM4_11 : 40|16@1+ (0.01,0) [0|655.35] "s"  IMM
 SG_ Reserved_11 : 56|8@1+ (1,0) [0|255] ""  IMM

BO_ 2332107932 M2I_Byrack_SUMDATA4__12: 8 MBMU
 SG_ CRC_M2I_Byrack_IMM4_12 : 0|8@1+ (1,0) [0|255] ""  IMM
 SG_ M2I_Byrack_HVS_IMM4_12 : 8|16@1+ (0.1,0) [0|6553.5] "v"  IMM
 SG_ M2I_Byrack_Enable_IMM4_12 : 24|2@1+ (1,0) [0|3] ""  IMM
 SG_ M2I_Byrack_ReVeEnable_IMM4_12 : 26|2@1+ (1,0) [0|3] ""  IMM
 SG_ Reserved_12 : 28|4@1+ (1,0) [0|15] ""  IMM
 SG_ M2I_Byrack_IsPostTm_IMM4_12 : 32|8@1+ (0.01,0) [0|2.55] "s"  IMM
 SG_ M2I_Byrack_SysABStTm_IMM4_12 : 40|16@1+ (0.01,0) [0|655.35] "s"  IMM
 SG_ Reserved_12 : 56|8@1+ (1,0) [0|255] ""  IMM

BO_ 2332107933 M2I_Byrack_SUMDATA4__13: 8 MBMU
 SG_ CRC_M2I_Byrack_IMM4_13 : 0|8@1+ (1,0) [0|255] ""  IMM
 SG_ M2I_Byrack_HVS_IMM4_13 : 8|16@1+ (0.1,0) [0|6553.5] "v"  IMM
 SG_ M2I_Byrack_Enable_IMM4_13 : 24|2@1+ (1,0) [0|3] ""  IMM
 SG_ M2I_Byrack_ReVeEnable_IMM4_13 : 26|2@1+ (1,0) [0|3] ""  IMM
 SG_ Reserved_13 : 28|4@1+ (1,0) [0|15] ""  IMM
 SG_ M2I_Byrack_IsPostTm_IMM4_13 : 32|8@1+ (0.01,0) [0|2.55] "s"  IMM
 SG_ M2I_Byrack_SysABStTm_IMM4_13 : 40|16@1+ (0.01,0) [0|655.35] "s"  IMM
 SG_ Reserved_13 : 56|8@1+ (1,0) [0|255] ""  IMM

BO_ 2332107934 M2I_Byrack_SUMDATA4__14: 8 MBMU
 SG_ CRC_M2I_Byrack_IMM4_14 : 0|8@1+ (1,0) [0|255] ""  IMM
 SG_ M2I_Byrack_HVS_IMM4_14 : 8|16@1+ (0.1,0) [0|6553.5] "v"  IMM
 SG_ M2I_Byrack_Enable_IMM4_14 : 24|2@1+ (1,0) [0|3] ""  IMM
 SG_ M2I_Byrack_ReVeEnable_IMM4_14 : 26|2@1+ (1,0) [0|3] ""  IMM
 SG_ Reserved_14 : 28|4@1+ (1,0) [0|15] ""  IMM
 SG_ M2I_Byrack_IsPostTm_IMM4_14 : 32|8@1+ (0.01,0) [0|2.55] "s"  IMM
 SG_ M2I_Byrack_SysABStTm_IMM4_14 : 40|16@1+ (0.01,0) [0|655.35] "s"  IMM
 SG_ Reserved_14 : 56|8@1+ (1,0) [0|255] ""  IMM

BO_ 2332107935 M2I_Byrack_SUMDATA4__15: 8 MBMU
 SG_ CRC_M2I_Byrack_IMM4_15 : 0|8@1+ (1,0) [0|255] ""  IMM
 SG_ M2I_Byrack_HVS_IMM4_15 : 8|16@1+ (0.1,0) [0|6553.5] "v"  IMM
 SG_ M2I_Byrack_Enable_IMM4_15 : 24|2@1+ (1,0) [0|3] ""  IMM
 SG_ M2I_Byrack_ReVeEnable_IMM4_15 : 26|2@1+ (1,0) [0|3] ""  IMM
 SG_ Reserved_15 : 28|4@1+ (1,0) [0|15] ""  IMM
 SG_ M2I_Byrack_IsPostTm_IMM4_15 : 32|8@1+ (0.01,0) [0|2.55] "s"  IMM
 SG_ M2I_Byrack_SysABStTm_IMM4_15 : 40|16@1+ (0.01,0) [0|655.35] "s"  IMM
 SG_ Reserved_15 : 56|8@1+ (1,0) [0|255] ""  IMM

BO_ 2332107936 M2I_Byrack_SUMDATA4__16: 8 MBMU
 SG_ CRC_M2I_Byrack_IMM4_16 : 0|8@1+ (1,0) [0|255] ""  IMM
 SG_ M2I_Byrack_HVS_IMM4_16 : 8|16@1+ (0.1,0) [0|6553.5] "v"  IMM
 SG_ M2I_Byrack_Enable_IMM4_16 : 24|2@1+ (1,0) [0|3] ""  IMM
 SG_ M2I_Byrack_ReVeEnable_IMM4_16 : 26|2@1+ (1,0) [0|3] ""  IMM
 SG_ Reserved_16 : 28|4@1+ (1,0) [0|15] ""  IMM
 SG_ M2I_Byrack_IsPostTm_IMM4_16 : 32|8@1+ (0.01,0) [0|2.55] "s"  IMM
 SG_ M2I_Byrack_SysABStTm_IMM4_16 : 40|16@1+ (0.01,0) [0|655.35] "s"  IMM
 SG_ Reserved_16 : 56|8@1+ (1,0) [0|255] ""  IMM

BO_ 2332107937 M2I_Byrack_SUMDATA4__17: 8 MBMU
 SG_ CRC_M2I_Byrack_IMM4_17 : 0|8@1+ (1,0) [0|255] ""  IMM
 SG_ M2I_Byrack_HVS_IMM4_17 : 8|16@1+ (0.1,0) [0|6553.5] "v"  IMM
 SG_ M2I_Byrack_Enable_IMM4_17 : 24|2@1+ (1,0) [0|3] ""  IMM
 SG_ M2I_Byrack_ReVeEnable_IMM4_17 : 26|2@1+ (1,0) [0|3] ""  IMM
 SG_ Reserved_17 : 28|4@1+ (1,0) [0|15] ""  IMM
 SG_ M2I_Byrack_IsPostTm_IMM4_17 : 32|8@1+ (0.01,0) [0|2.55] "s"  IMM
 SG_ M2I_Byrack_SysABStTm_IMM4_17 : 40|16@1+ (0.01,0) [0|655.35] "s"  IMM
 SG_ Reserved_17 : 56|8@1+ (1,0) [0|255] ""  IMM

BO_ 2332107938 M2I_Byrack_SUMDATA4__18: 8 MBMU
 SG_ CRC_M2I_Byrack_IMM4_18 : 0|8@1+ (1,0) [0|255] ""  IMM
 SG_ M2I_Byrack_HVS_IMM4_18 : 8|16@1+ (0.1,0) [0|6553.5] "v"  IMM
 SG_ M2I_Byrack_Enable_IMM4_18 : 24|2@1+ (1,0) [0|3] ""  IMM
 SG_ M2I_Byrack_ReVeEnable_IMM4_18 : 26|2@1+ (1,0) [0|3] ""  IMM
 SG_ Reserved_18 : 28|4@1+ (1,0) [0|15] ""  IMM
 SG_ M2I_Byrack_IsPostTm_IMM4_18 : 32|8@1+ (0.01,0) [0|2.55] "s"  IMM
 SG_ M2I_Byrack_SysABStTm_IMM4_18 : 40|16@1+ (0.01,0) [0|655.35] "s"  IMM
 SG_ Reserved_18 : 56|8@1+ (1,0) [0|255] ""  IMM

BO_ 2332107939 M2I_Byrack_SUMDATA4__19: 8 MBMU
 SG_ CRC_M2I_Byrack_IMM4_19 : 0|8@1+ (1,0) [0|255] ""  IMM
 SG_ M2I_Byrack_HVS_IMM4_19 : 8|16@1+ (0.1,0) [0|6553.5] "v"  IMM
 SG_ M2I_Byrack_Enable_IMM4_19 : 24|2@1+ (1,0) [0|3] ""  IMM
 SG_ M2I_Byrack_ReVeEnable_IMM4_19 : 26|2@1+ (1,0) [0|3] ""  IMM
 SG_ Reserved_19 : 28|4@1+ (1,0) [0|15] ""  IMM
 SG_ M2I_Byrack_IsPostTm_IMM4_19 : 32|8@1+ (0.01,0) [0|2.55] "s"  IMM
 SG_ M2I_Byrack_SysABStTm_IMM4_19 : 40|16@1+ (0.01,0) [0|655.35] "s"  IMM
 SG_ Reserved_19 : 56|8@1+ (1,0) [0|255] ""  IMM

BO_ 2332107940 M2I_Byrack_SUMDATA4__20: 8 MBMU
 SG_ CRC_M2I_Byrack_IMM4_20 : 0|8@1+ (1,0) [0|255] ""  IMM
 SG_ M2I_Byrack_HVS_IMM4_20 : 8|16@1+ (0.1,0) [0|6553.5] "v"  IMM
 SG_ M2I_Byrack_Enable_IMM4_20 : 24|2@1+ (1,0) [0|3] ""  IMM
 SG_ M2I_Byrack_ReVeEnable_IMM4_20 : 26|2@1+ (1,0) [0|3] ""  IMM
 SG_ Reserved_20 : 28|4@1+ (1,0) [0|15] ""  IMM
 SG_ M2I_Byrack_IsPostTm_IMM4_20 : 32|8@1+ (0.01,0) [0|2.55] "s"  IMM
 SG_ M2I_Byrack_SysABStTm_IMM4_20 : 40|16@1+ (0.01,0) [0|655.35] "s"  IMM
 SG_ Reserved_20 : 56|8@1+ (1,0) [0|255] ""  IMM

BO_ 2332107941 M2I_Byrack_SUMDATA4__21: 8 MBMU
 SG_ CRC_M2I_Byrack_IMM4_21 : 0|8@1+ (1,0) [0|255] ""  IMM
 SG_ M2I_Byrack_HVS_IMM4_21 : 8|16@1+ (0.1,0) [0|6553.5] "v"  IMM
 SG_ M2I_Byrack_Enable_IMM4_21 : 24|2@1+ (1,0) [0|3] ""  IMM
 SG_ M2I_Byrack_ReVeEnable_IMM4_21 : 26|2@1+ (1,0) [0|3] ""  IMM
 SG_ Reserved_21 : 28|4@1+ (1,0) [0|15] ""  IMM
 SG_ M2I_Byrack_IsPostTm_IMM4_21 : 32|8@1+ (0.01,0) [0|2.55] "s"  IMM
 SG_ M2I_Byrack_SysABStTm_IMM4_21 : 40|16@1+ (0.01,0) [0|655.35] "s"  IMM
 SG_ Reserved_21 : 56|8@1+ (1,0) [0|255] ""  IMM

BO_ 2332107942 M2I_Byrack_SUMDATA4__22: 8 MBMU
 SG_ CRC_M2I_Byrack_IMM4_22 : 0|8@1+ (1,0) [0|255] ""  IMM
 SG_ M2I_Byrack_HVS_IMM4_22 : 8|16@1+ (0.1,0) [0|6553.5] "v"  IMM
 SG_ M2I_Byrack_Enable_IMM4_22 : 24|2@1+ (1,0) [0|3] ""  IMM
 SG_ M2I_Byrack_ReVeEnable_IMM4_22 : 26|2@1+ (1,0) [0|3] ""  IMM
 SG_ Reserved_22 : 28|4@1+ (1,0) [0|15] ""  IMM
 SG_ M2I_Byrack_IsPostTm_IMM4_22 : 32|8@1+ (0.01,0) [0|2.55] "s"  IMM
 SG_ M2I_Byrack_SysABStTm_IMM4_22 : 40|16@1+ (0.01,0) [0|655.35] "s"  IMM
 SG_ Reserved_22 : 56|8@1+ (1,0) [0|255] ""  IMM

BO_ 2332107943 M2I_Byrack_SUMDATA4__23: 8 MBMU
 SG_ CRC_M2I_Byrack_IMM4_23 : 0|8@1+ (1,0) [0|255] ""  IMM
 SG_ M2I_Byrack_HVS_IMM4_23 : 8|16@1+ (0.1,0) [0|6553.5] "v"  IMM
 SG_ M2I_Byrack_Enable_IMM4_23 : 24|2@1+ (1,0) [0|3] ""  IMM
 SG_ M2I_Byrack_ReVeEnable_IMM4_23 : 26|2@1+ (1,0) [0|3] ""  IMM
 SG_ Reserved_23 : 28|4@1+ (1,0) [0|15] ""  IMM
 SG_ M2I_Byrack_IsPostTm_IMM4_23 : 32|8@1+ (0.01,0) [0|2.55] "s"  IMM
 SG_ M2I_Byrack_SysABStTm_IMM4_23 : 40|16@1+ (0.01,0) [0|655.35] "s"  IMM
 SG_ Reserved_23 : 56|8@1+ (1,0) [0|255] ""  IMM

BO_ 2332107944 M2I_Byrack_SUMDATA4__24: 8 MBMU
 SG_ CRC_M2I_Byrack_IMM4_24 : 0|8@1+ (1,0) [0|255] ""  IMM
 SG_ M2I_Byrack_HVS_IMM4_24 : 8|16@1+ (0.1,0) [0|6553.5] "v"  IMM
 SG_ M2I_Byrack_Enable_IMM4_24 : 24|2@1+ (1,0) [0|3] ""  IMM
 SG_ M2I_Byrack_ReVeEnable_IMM4_24 : 26|2@1+ (1,0) [0|3] ""  IMM
 SG_ Reserved_24 : 28|4@1+ (1,0) [0|15] ""  IMM
 SG_ M2I_Byrack_IsPostTm_IMM4_24 : 32|8@1+ (0.01,0) [0|2.55] "s"  IMM
 SG_ M2I_Byrack_SysABStTm_IMM4_24 : 40|16@1+ (0.01,0) [0|655.35] "s"  IMM
 SG_ Reserved_24 : 56|8@1+ (1,0) [0|255] ""  IMM

BO_ 2332107945 M2I_Byrack_SUMDATA4__25: 8 MBMU
 SG_ CRC_M2I_Byrack_IMM4_25 : 0|8@1+ (1,0) [0|255] ""  IMM
 SG_ M2I_Byrack_HVS_IMM4_25 : 8|16@1+ (0.1,0) [0|6553.5] "v"  IMM
 SG_ M2I_Byrack_Enable_IMM4_25 : 24|2@1+ (1,0) [0|3] ""  IMM
 SG_ M2I_Byrack_ReVeEnable_IMM4_25 : 26|2@1+ (1,0) [0|3] ""  IMM
 SG_ Reserved_25 : 28|4@1+ (1,0) [0|15] ""  IMM
 SG_ M2I_Byrack_IsPostTm_IMM4_25 : 32|8@1+ (0.01,0) [0|2.55] "s"  IMM
 SG_ M2I_Byrack_SysABStTm_IMM4_25 : 40|16@1+ (0.01,0) [0|655.35] "s"  IMM
 SG_ Reserved_25 : 56|8@1+ (1,0) [0|255] ""  IMM

BO_ 2332107946 M2I_Byrack_SUMDATA4__26: 8 MBMU
 SG_ CRC_M2I_Byrack_IMM4_26 : 0|8@1+ (1,0) [0|255] ""  IMM
 SG_ M2I_Byrack_HVS_IMM4_26 : 8|16@1+ (0.1,0) [0|6553.5] "v"  IMM
 SG_ M2I_Byrack_Enable_IMM4_26 : 24|2@1+ (1,0) [0|3] ""  IMM
 SG_ M2I_Byrack_ReVeEnable_IMM4_26 : 26|2@1+ (1,0) [0|3] ""  IMM
 SG_ Reserved_26 : 28|4@1+ (1,0) [0|15] ""  IMM
 SG_ M2I_Byrack_IsPostTm_IMM4_26 : 32|8@1+ (0.01,0) [0|2.55] "s"  IMM
 SG_ M2I_Byrack_SysABStTm_IMM4_26 : 40|16@1+ (0.01,0) [0|655.35] "s"  IMM
 SG_ Reserved_26 : 56|8@1+ (1,0) [0|255] ""  IMM

BO_ 2332107947 M2I_Byrack_SUMDATA4__27: 8 MBMU
 SG_ CRC_M2I_Byrack_IMM4_27 : 0|8@1+ (1,0) [0|255] ""  IMM
 SG_ M2I_Byrack_HVS_IMM4_27 : 8|16@1+ (0.1,0) [0|6553.5] "v"  IMM
 SG_ M2I_Byrack_Enable_IMM4_27 : 24|2@1+ (1,0) [0|3] ""  IMM
 SG_ M2I_Byrack_ReVeEnable_IMM4_27 : 26|2@1+ (1,0) [0|3] ""  IMM
 SG_ Reserved_27 : 28|4@1+ (1,0) [0|15] ""  IMM
 SG_ M2I_Byrack_IsPostTm_IMM4_27 : 32|8@1+ (0.01,0) [0|2.55] "s"  IMM
 SG_ M2I_Byrack_SysABStTm_IMM4_27 : 40|16@1+ (0.01,0) [0|655.35] "s"  IMM
 SG_ Reserved_27 : 56|8@1+ (1,0) [0|255] ""  IMM

BO_ 2332107948 M2I_Byrack_SUMDATA4__28: 8 MBMU
 SG_ CRC_M2I_Byrack_IMM4_28 : 0|8@1+ (1,0) [0|255] ""  IMM
 SG_ M2I_Byrack_HVS_IMM4_28 : 8|16@1+ (0.1,0) [0|6553.5] "v"  IMM
 SG_ M2I_Byrack_Enable_IMM4_28 : 24|2@1+ (1,0) [0|3] ""  IMM
 SG_ M2I_Byrack_ReVeEnable_IMM4_28 : 26|2@1+ (1,0) [0|3] ""  IMM
 SG_ Reserved_28 : 28|4@1+ (1,0) [0|15] ""  IMM
 SG_ M2I_Byrack_IsPostTm_IMM4_28 : 32|8@1+ (0.01,0) [0|2.55] "s"  IMM
 SG_ M2I_Byrack_SysABStTm_IMM4_28 : 40|16@1+ (0.01,0) [0|655.35] "s"  IMM
 SG_ Reserved_28 : 56|8@1+ (1,0) [0|255] ""  IMM

BO_ 2332107949 M2I_Byrack_SUMDATA4__29: 8 MBMU
 SG_ CRC_M2I_Byrack_IMM4_29 : 0|8@1+ (1,0) [0|255] ""  IMM
 SG_ M2I_Byrack_HVS_IMM4_29 : 8|16@1+ (0.1,0) [0|6553.5] "v"  IMM
 SG_ M2I_Byrack_Enable_IMM4_29 : 24|2@1+ (1,0) [0|3] ""  IMM
 SG_ M2I_Byrack_ReVeEnable_IMM4_29 : 26|2@1+ (1,0) [0|3] ""  IMM
 SG_ Reserved_29 : 28|4@1+ (1,0) [0|15] ""  IMM
 SG_ M2I_Byrack_IsPostTm_IMM4_29 : 32|8@1+ (0.01,0) [0|2.55] "s"  IMM
 SG_ M2I_Byrack_SysABStTm_IMM4_29 : 40|16@1+ (0.01,0) [0|655.35] "s"  IMM
 SG_ Reserved_29 : 56|8@1+ (1,0) [0|255] ""  IMM

BO_ 2332107950 M2I_Byrack_SUMDATA4__30: 8 MBMU
 SG_ CRC_M2I_Byrack_IMM4_30 : 0|8@1+ (1,0) [0|255] ""  IMM
 SG_ M2I_Byrack_HVS_IMM4_30 : 8|16@1+ (0.1,0) [0|6553.5] "v"  IMM
 SG_ M2I_Byrack_Enable_IMM4_30 : 24|2@1+ (1,0) [0|3] ""  IMM
 SG_ M2I_Byrack_ReVeEnable_IMM4_30 : 26|2@1+ (1,0) [0|3] ""  IMM
 SG_ Reserved_30 : 28|4@1+ (1,0) [0|15] ""  IMM
 SG_ M2I_Byrack_IsPostTm_IMM4_30 : 32|8@1+ (0.01,0) [0|2.55] "s"  IMM
 SG_ M2I_Byrack_SysABStTm_IMM4_30 : 40|16@1+ (0.01,0) [0|655.35] "s"  IMM
 SG_ Reserved_30 : 56|8@1+ (1,0) [0|255] ""  IMM

BO_ 2332107951 M2I_Byrack_SUMDATA4__31: 8 MBMU
 SG_ CRC_M2I_Byrack_IMM4_31 : 0|8@1+ (1,0) [0|255] ""  IMM
 SG_ M2I_Byrack_HVS_IMM4_31 : 8|16@1+ (0.1,0) [0|6553.5] "v"  IMM
 SG_ M2I_Byrack_Enable_IMM4_31 : 24|2@1+ (1,0) [0|3] ""  IMM
 SG_ M2I_Byrack_ReVeEnable_IMM4_31 : 26|2@1+ (1,0) [0|3] ""  IMM
 SG_ Reserved_31 : 28|4@1+ (1,0) [0|15] ""  IMM
 SG_ M2I_Byrack_IsPostTm_IMM4_31 : 32|8@1+ (0.01,0) [0|2.55] "s"  IMM
 SG_ M2I_Byrack_SysABStTm_IMM4_31 : 40|16@1+ (0.01,0) [0|655.35] "s"  IMM
 SG_ Reserved_31 : 56|8@1+ (1,0) [0|255] ""  IMM

BO_ 2332108177 M2I_Byrack_SUMDATA5__01: 8 MBMU
 SG_ CRC_M2I_Byrack_IMM5_01 : 0|8@1+ (1,0) [0|255] ""  IMM
 SG_ M2I_Byrack_HVS_IMM5_01 : 8|16@1+ (0.1,0) [0|6553.5] "v"  IMM
 SG_ M2I_Byrack_Enable_IMM5_01 : 24|2@1+ (1,0) [0|3] ""  IMM
 SG_ M2I_Byrack_ReVeEnable_IMM5_01 : 26|2@1+ (1,0) [0|3] ""  IMM
 SG_ Reserved_01 : 28|4@1+ (1,0) [0|15] ""  IMM
 SG_ M2I_Byrack_IsPostTm_IMM5_01 : 32|8@1+ (0.01,0) [0|2.55] "s"  IMM
 SG_ M2I_Byrack_SysABStTm_IMM5_01 : 40|16@1+ (0.01,0) [0|655.35] "s"  IMM
 SG_ Reserved_01 : 56|8@1+ (1,0) [0|255] ""  IMM

BO_ 2332108178 M2I_Byrack_SUMDATA5__02: 8 MBMU
 SG_ CRC_M2I_Byrack_IMM5_02 : 0|8@1+ (1,0) [0|255] ""  IMM
 SG_ M2I_Byrack_HVS_IMM5_02 : 8|16@1+ (0.1,0) [0|6553.5] "v"  IMM
 SG_ M2I_Byrack_Enable_IMM5_02 : 24|2@1+ (1,0) [0|3] ""  IMM
 SG_ M2I_Byrack_ReVeEnable_IMM5_02 : 26|2@1+ (1,0) [0|3] ""  IMM
 SG_ Reserved_02 : 28|4@1+ (1,0) [0|15] ""  IMM
 SG_ M2I_Byrack_IsPostTm_IMM5_02 : 32|8@1+ (0.01,0) [0|2.55] "s"  IMM
 SG_ M2I_Byrack_SysABStTm_IMM5_02 : 40|16@1+ (0.01,0) [0|655.35] "s"  IMM
 SG_ Reserved_02 : 56|8@1+ (1,0) [0|255] ""  IMM

BO_ 2332108179 M2I_Byrack_SUMDATA5__03: 8 MBMU
 SG_ CRC_M2I_Byrack_IMM5_03 : 0|8@1+ (1,0) [0|255] ""  IMM
 SG_ M2I_Byrack_HVS_IMM5_03 : 8|16@1+ (0.1,0) [0|6553.5] "v"  IMM
 SG_ M2I_Byrack_Enable_IMM5_03 : 24|2@1+ (1,0) [0|3] ""  IMM
 SG_ M2I_Byrack_ReVeEnable_IMM5_03 : 26|2@1+ (1,0) [0|3] ""  IMM
 SG_ Reserved_03 : 28|4@1+ (1,0) [0|15] ""  IMM
 SG_ M2I_Byrack_IsPostTm_IMM5_03 : 32|8@1+ (0.01,0) [0|2.55] "s"  IMM
 SG_ M2I_Byrack_SysABStTm_IMM5_03 : 40|16@1+ (0.01,0) [0|655.35] "s"  IMM
 SG_ Reserved_03 : 56|8@1+ (1,0) [0|255] ""  IMM

BO_ 2332108180 M2I_Byrack_SUMDATA5__04: 8 MBMU
 SG_ CRC_M2I_Byrack_IMM5_04 : 0|8@1+ (1,0) [0|255] ""  IMM
 SG_ M2I_Byrack_HVS_IMM5_04 : 8|16@1+ (0.1,0) [0|6553.5] "v"  IMM
 SG_ M2I_Byrack_Enable_IMM5_04 : 24|2@1+ (1,0) [0|3] ""  IMM
 SG_ M2I_Byrack_ReVeEnable_IMM5_04 : 26|2@1+ (1,0) [0|3] ""  IMM
 SG_ Reserved_04 : 28|4@1+ (1,0) [0|15] ""  IMM
 SG_ M2I_Byrack_IsPostTm_IMM5_04 : 32|8@1+ (0.01,0) [0|2.55] "s"  IMM
 SG_ M2I_Byrack_SysABStTm_IMM5_04 : 40|16@1+ (0.01,0) [0|655.35] "s"  IMM
 SG_ Reserved_04 : 56|8@1+ (1,0) [0|255] ""  IMM

BO_ 2332108181 M2I_Byrack_SUMDATA5__05: 8 MBMU
 SG_ CRC_M2I_Byrack_IMM5_05 : 0|8@1+ (1,0) [0|255] ""  IMM
 SG_ M2I_Byrack_HVS_IMM5_05 : 8|16@1+ (0.1,0) [0|6553.5] "v"  IMM
 SG_ M2I_Byrack_Enable_IMM5_05 : 24|2@1+ (1,0) [0|3] ""  IMM
 SG_ M2I_Byrack_ReVeEnable_IMM5_05 : 26|2@1+ (1,0) [0|3] ""  IMM
 SG_ Reserved_05 : 28|4@1+ (1,0) [0|15] ""  IMM
 SG_ M2I_Byrack_IsPostTm_IMM5_05 : 32|8@1+ (0.01,0) [0|2.55] "s"  IMM
 SG_ M2I_Byrack_SysABStTm_IMM5_05 : 40|16@1+ (0.01,0) [0|655.35] "s"  IMM
 SG_ Reserved_05 : 56|8@1+ (1,0) [0|255] ""  IMM

BO_ 2332108182 M2I_Byrack_SUMDATA5__06: 8 MBMU
 SG_ CRC_M2I_Byrack_IMM5_06 : 0|8@1+ (1,0) [0|255] ""  IMM
 SG_ M2I_Byrack_HVS_IMM5_06 : 8|16@1+ (0.1,0) [0|6553.5] "v"  IMM
 SG_ M2I_Byrack_Enable_IMM5_06 : 24|2@1+ (1,0) [0|3] ""  IMM
 SG_ M2I_Byrack_ReVeEnable_IMM5_06 : 26|2@1+ (1,0) [0|3] ""  IMM
 SG_ Reserved_06 : 28|4@1+ (1,0) [0|15] ""  IMM
 SG_ M2I_Byrack_IsPostTm_IMM5_06 : 32|8@1+ (0.01,0) [0|2.55] "s"  IMM
 SG_ M2I_Byrack_SysABStTm_IMM5_06 : 40|16@1+ (0.01,0) [0|655.35] "s"  IMM
 SG_ Reserved_06 : 56|8@1+ (1,0) [0|255] ""  IMM

BO_ 2332108183 M2I_Byrack_SUMDATA5__07: 8 MBMU
 SG_ CRC_M2I_Byrack_IMM5_07 : 0|8@1+ (1,0) [0|255] ""  IMM
 SG_ M2I_Byrack_HVS_IMM5_07 : 8|16@1+ (0.1,0) [0|6553.5] "v"  IMM
 SG_ M2I_Byrack_Enable_IMM5_07 : 24|2@1+ (1,0) [0|3] ""  IMM
 SG_ M2I_Byrack_ReVeEnable_IMM5_07 : 26|2@1+ (1,0) [0|3] ""  IMM
 SG_ Reserved_07 : 28|4@1+ (1,0) [0|15] ""  IMM
 SG_ M2I_Byrack_IsPostTm_IMM5_07 : 32|8@1+ (0.01,0) [0|2.55] "s"  IMM
 SG_ M2I_Byrack_SysABStTm_IMM5_07 : 40|16@1+ (0.01,0) [0|655.35] "s"  IMM
 SG_ Reserved_07 : 56|8@1+ (1,0) [0|255] ""  IMM

BO_ 2332108184 M2I_Byrack_SUMDATA5__08: 8 MBMU
 SG_ CRC_M2I_Byrack_IMM5_08 : 0|8@1+ (1,0) [0|255] ""  IMM
 SG_ M2I_Byrack_HVS_IMM5_08 : 8|16@1+ (0.1,0) [0|6553.5] "v"  IMM
 SG_ M2I_Byrack_Enable_IMM5_08 : 24|2@1+ (1,0) [0|3] ""  IMM
 SG_ M2I_Byrack_ReVeEnable_IMM5_08 : 26|2@1+ (1,0) [0|3] ""  IMM
 SG_ Reserved_08 : 28|4@1+ (1,0) [0|15] ""  IMM
 SG_ M2I_Byrack_IsPostTm_IMM5_08 : 32|8@1+ (0.01,0) [0|2.55] "s"  IMM
 SG_ M2I_Byrack_SysABStTm_IMM5_08 : 40|16@1+ (0.01,0) [0|655.35] "s"  IMM
 SG_ Reserved_08 : 56|8@1+ (1,0) [0|255] ""  IMM

BO_ 2332108185 M2I_Byrack_SUMDATA5__09: 8 MBMU
 SG_ CRC_M2I_Byrack_IMM5_09 : 0|8@1+ (1,0) [0|255] ""  IMM
 SG_ M2I_Byrack_HVS_IMM5_09 : 8|16@1+ (0.1,0) [0|6553.5] "v"  IMM
 SG_ M2I_Byrack_Enable_IMM5_09 : 24|2@1+ (1,0) [0|3] ""  IMM
 SG_ M2I_Byrack_ReVeEnable_IMM5_09 : 26|2@1+ (1,0) [0|3] ""  IMM
 SG_ Reserved_09 : 28|4@1+ (1,0) [0|15] ""  IMM
 SG_ M2I_Byrack_IsPostTm_IMM5_09 : 32|8@1+ (0.01,0) [0|2.55] "s"  IMM
 SG_ M2I_Byrack_SysABStTm_IMM5_09 : 40|16@1+ (0.01,0) [0|655.35] "s"  IMM
 SG_ Reserved_09 : 56|8@1+ (1,0) [0|255] ""  IMM

BO_ 2332108186 M2I_Byrack_SUMDATA5__10: 8 MBMU
 SG_ CRC_M2I_Byrack_IMM5_10 : 0|8@1+ (1,0) [0|255] ""  IMM
 SG_ M2I_Byrack_HVS_IMM5_10 : 8|16@1+ (0.1,0) [0|6553.5] "v"  IMM
 SG_ M2I_Byrack_Enable_IMM5_10 : 24|2@1+ (1,0) [0|3] ""  IMM
 SG_ M2I_Byrack_ReVeEnable_IMM5_10 : 26|2@1+ (1,0) [0|3] ""  IMM
 SG_ Reserved_10 : 28|4@1+ (1,0) [0|15] ""  IMM
 SG_ M2I_Byrack_IsPostTm_IMM5_10 : 32|8@1+ (0.01,0) [0|2.55] "s"  IMM
 SG_ M2I_Byrack_SysABStTm_IMM5_10 : 40|16@1+ (0.01,0) [0|655.35] "s"  IMM
 SG_ Reserved_10 : 56|8@1+ (1,0) [0|255] ""  IMM

BO_ 2332108187 M2I_Byrack_SUMDATA5__11: 8 MBMU
 SG_ CRC_M2I_Byrack_IMM5_11 : 0|8@1+ (1,0) [0|255] ""  IMM
 SG_ M2I_Byrack_HVS_IMM5_11 : 8|16@1+ (0.1,0) [0|6553.5] "v"  IMM
 SG_ M2I_Byrack_Enable_IMM5_11 : 24|2@1+ (1,0) [0|3] ""  IMM
 SG_ M2I_Byrack_ReVeEnable_IMM5_11 : 26|2@1+ (1,0) [0|3] ""  IMM
 SG_ Reserved_11 : 28|4@1+ (1,0) [0|15] ""  IMM
 SG_ M2I_Byrack_IsPostTm_IMM5_11 : 32|8@1+ (0.01,0) [0|2.55] "s"  IMM
 SG_ M2I_Byrack_SysABStTm_IMM5_11 : 40|16@1+ (0.01,0) [0|655.35] "s"  IMM
 SG_ Reserved_11 : 56|8@1+ (1,0) [0|255] ""  IMM

BO_ 2332108188 M2I_Byrack_SUMDATA5__12: 8 MBMU
 SG_ CRC_M2I_Byrack_IMM5_12 : 0|8@1+ (1,0) [0|255] ""  IMM
 SG_ M2I_Byrack_HVS_IMM5_12 : 8|16@1+ (0.1,0) [0|6553.5] "v"  IMM
 SG_ M2I_Byrack_Enable_IMM5_12 : 24|2@1+ (1,0) [0|3] ""  IMM
 SG_ M2I_Byrack_ReVeEnable_IMM5_12 : 26|2@1+ (1,0) [0|3] ""  IMM
 SG_ Reserved_12 : 28|4@1+ (1,0) [0|15] ""  IMM
 SG_ M2I_Byrack_IsPostTm_IMM5_12 : 32|8@1+ (0.01,0) [0|2.55] "s"  IMM
 SG_ M2I_Byrack_SysABStTm_IMM5_12 : 40|16@1+ (0.01,0) [0|655.35] "s"  IMM
 SG_ Reserved_12 : 56|8@1+ (1,0) [0|255] ""  IMM

BO_ 2332108189 M2I_Byrack_SUMDATA5__13: 8 MBMU
 SG_ CRC_M2I_Byrack_IMM5_13 : 0|8@1+ (1,0) [0|255] ""  IMM
 SG_ M2I_Byrack_HVS_IMM5_13 : 8|16@1+ (0.1,0) [0|6553.5] "v"  IMM
 SG_ M2I_Byrack_Enable_IMM5_13 : 24|2@1+ (1,0) [0|3] ""  IMM
 SG_ M2I_Byrack_ReVeEnable_IMM5_13 : 26|2@1+ (1,0) [0|3] ""  IMM
 SG_ Reserved_13 : 28|4@1+ (1,0) [0|15] ""  IMM
 SG_ M2I_Byrack_IsPostTm_IMM5_13 : 32|8@1+ (0.01,0) [0|2.55] "s"  IMM
 SG_ M2I_Byrack_SysABStTm_IMM5_13 : 40|16@1+ (0.01,0) [0|655.35] "s"  IMM
 SG_ Reserved_13 : 56|8@1+ (1,0) [0|255] ""  IMM

BO_ 2332108190 M2I_Byrack_SUMDATA5__14: 8 MBMU
 SG_ CRC_M2I_Byrack_IMM5_14 : 0|8@1+ (1,0) [0|255] ""  IMM
 SG_ M2I_Byrack_HVS_IMM5_14 : 8|16@1+ (0.1,0) [0|6553.5] "v"  IMM
 SG_ M2I_Byrack_Enable_IMM5_14 : 24|2@1+ (1,0) [0|3] ""  IMM
 SG_ M2I_Byrack_ReVeEnable_IMM5_14 : 26|2@1+ (1,0) [0|3] ""  IMM
 SG_ Reserved_14 : 28|4@1+ (1,0) [0|15] ""  IMM
 SG_ M2I_Byrack_IsPostTm_IMM5_14 : 32|8@1+ (0.01,0) [0|2.55] "s"  IMM
 SG_ M2I_Byrack_SysABStTm_IMM5_14 : 40|16@1+ (0.01,0) [0|655.35] "s"  IMM
 SG_ Reserved_14 : 56|8@1+ (1,0) [0|255] ""  IMM

CM_ SG_ 2332155942 I2A_Byrack_SUMDATA1_CRC_06 "IMM发送的概要数据1的CRC";
CM_ SG_ 2332155942 I2A_Byrack_SUMDATA1_ALIV_06 "IMM发送的概要数据1的生命信号，0~15循环";
CM_ SG_ 2332155942 I2A_Byrack_VoltVld_06 "IMM采样有效标志";
CM_ SG_ 2332155942 I2A_Byrack_VoltErr_06 "IMM板电源故障标志(暂未使用）";
CM_ SG_ 2332155942 I2A_Byrack_InsResValid_06 "IMM绝缘阻值有效性";
CM_ SG_ 2332155942 Reserved_06 "预留";
CM_ SG_ 2332155942 I2A_Byrack_IsoResPos_06 "主正对机壳的有效绝缘阻值";
CM_ SG_ 2332155942 I2A_Byrack_IsoResNeg_06 "主负对机壳的有效绝缘阻值";
CM_ SG_ 2332155943 I2A_Byrack_SUMDATA1_CRC_07 "IMM发送的概要数据1的CRC";
CM_ SG_ 2332155943 I2A_Byrack_SUMDATA1_ALIV_07 "IMM发送的概要数据1的生命信号，0~15循环";
CM_ SG_ 2332155943 I2A_Byrack_VoltVld_07 "IMM采样有效标志";
CM_ SG_ 2332155943 I2A_Byrack_VoltErr_07 "IMM板电源故障标志(暂未使用）";
CM_ SG_ 2332155943 I2A_Byrack_InsResValid_07 "IMM绝缘阻值有效性";
CM_ SG_ 2332155943 Reserved_07 "预留";
CM_ SG_ 2332155943 I2A_Byrack_IsoResPos_07 "主正对机壳的有效绝缘阻值";
CM_ SG_ 2332155943 I2A_Byrack_IsoResNeg_07 "主负对机壳的有效绝缘阻值";
CM_ SG_ 2332155944 I2A_Byrack_SUMDATA1_CRC_08 "IMM发送的概要数据1的CRC";
CM_ SG_ 2332155944 I2A_Byrack_SUMDATA1_ALIV_08 "IMM发送的概要数据1的生命信号，0~15循环";
CM_ SG_ 2332155944 I2A_Byrack_VoltVld_08 "IMM采样有效标志";
CM_ SG_ 2332155944 I2A_Byrack_VoltErr_08 "IMM板电源故障标志(暂未使用）";
CM_ SG_ 2332155944 I2A_Byrack_InsResValid_08 "IMM绝缘阻值有效性";
CM_ SG_ 2332155944 Reserved_08 "预留";
CM_ SG_ 2332155944 I2A_Byrack_IsoResPos_08 "主正对机壳的有效绝缘阻值";
CM_ SG_ 2332155944 I2A_Byrack_IsoResNeg_08 "主负对机壳的有效绝缘阻值";
CM_ SG_ 2332155945 I2A_Byrack_SUMDATA1_CRC_09 "IMM发送的概要数据1的CRC";
CM_ SG_ 2332155945 I2A_Byrack_SUMDATA1_ALIV_09 "IMM发送的概要数据1的生命信号，0~15循环";
CM_ SG_ 2332155945 I2A_Byrack_VoltVld_09 "IMM采样有效标志";
CM_ SG_ 2332155945 I2A_Byrack_VoltErr_09 "IMM板电源故障标志(暂未使用）";
CM_ SG_ 2332155945 I2A_Byrack_InsResValid_09 "IMM绝缘阻值有效性";
CM_ SG_ 2332155945 Reserved_09 "预留";
CM_ SG_ 2332155945 I2A_Byrack_IsoResPos_09 "主正对机壳的有效绝缘阻值";
CM_ SG_ 2332155945 I2A_Byrack_IsoResNeg_09 "主负对机壳的有效绝缘阻值";
CM_ SG_ 2332155946 I2A_Byrack_SUMDATA1_CRC_10 "IMM发送的概要数据1的CRC";
CM_ SG_ 2332155946 I2A_Byrack_SUMDATA1_ALIV_10 "IMM发送的概要数据1的生命信号，0~15循环";
CM_ SG_ 2332155946 I2A_Byrack_VoltVld_10 "IMM采样有效标志";
CM_ SG_ 2332155946 I2A_Byrack_VoltErr_10 "IMM板电源故障标志(暂未使用）";
CM_ SG_ 2332155946 I2A_Byrack_InsResValid_10 "IMM绝缘阻值有效性";
CM_ SG_ 2332155946 Reserved_10 "预留";
CM_ SG_ 2332155946 I2A_Byrack_IsoResPos_10 "主正对机壳的有效绝缘阻值";
CM_ SG_ 2332155946 I2A_Byrack_IsoResNeg_10 "主负对机壳的有效绝缘阻值";
CM_ SG_ 2332155947 I2A_Byrack_SUMDATA1_CRC_11 "IMM发送的概要数据1的CRC";
CM_ SG_ 2332155947 I2A_Byrack_SUMDATA1_ALIV_11 "IMM发送的概要数据1的生命信号，0~15循环";
CM_ SG_ 2332155947 I2A_Byrack_VoltVld_11 "IMM采样有效标志";
CM_ SG_ 2332155947 I2A_Byrack_VoltErr_11 "IMM板电源故障标志(暂未使用）";
CM_ SG_ 2332155947 I2A_Byrack_InsResValid_11 "IMM绝缘阻值有效性";
CM_ SG_ 2332155947 Reserved_11 "预留";
CM_ SG_ 2332155947 I2A_Byrack_IsoResPos_11 "主正对机壳的有效绝缘阻值";
CM_ SG_ 2332155947 I2A_Byrack_IsoResNeg_11 "主负对机壳的有效绝缘阻值";
CM_ SG_ 2332155948 I2A_Byrack_SUMDATA1_CRC_12 "IMM发送的概要数据1的CRC";
CM_ SG_ 2332155948 I2A_Byrack_SUMDATA1_ALIV_12 "IMM发送的概要数据1的生命信号，0~15循环";
CM_ SG_ 2332155948 I2A_Byrack_VoltVld_12 "IMM采样有效标志";
CM_ SG_ 2332155948 I2A_Byrack_VoltErr_12 "IMM板电源故障标志(暂未使用）";
CM_ SG_ 2332155948 I2A_Byrack_InsResValid_12 "IMM绝缘阻值有效性";
CM_ SG_ 2332155948 Reserved_12 "预留";
CM_ SG_ 2332155948 I2A_Byrack_IsoResPos_12 "主正对机壳的有效绝缘阻值";
CM_ SG_ 2332155948 I2A_Byrack_IsoResNeg_12 "主负对机壳的有效绝缘阻值";
CM_ SG_ 2332155949 I2A_Byrack_SUMDATA1_CRC_13 "IMM发送的概要数据1的CRC";
CM_ SG_ 2332155949 I2A_Byrack_SUMDATA1_ALIV_13 "IMM发送的概要数据1的生命信号，0~15循环";
CM_ SG_ 2332155949 I2A_Byrack_VoltVld_13 "IMM采样有效标志";
CM_ SG_ 2332155949 I2A_Byrack_VoltErr_13 "IMM板电源故障标志(暂未使用）";
CM_ SG_ 2332155949 I2A_Byrack_InsResValid_13 "IMM绝缘阻值有效性";
CM_ SG_ 2332155949 Reserved_13 "预留";
CM_ SG_ 2332155949 I2A_Byrack_IsoResPos_13 "主正对机壳的有效绝缘阻值";
CM_ SG_ 2332155949 I2A_Byrack_IsoResNeg_13 "主负对机壳的有效绝缘阻值";
CM_ SG_ 2332155950 I2A_Byrack_SUMDATA1_CRC_14 "IMM发送的概要数据1的CRC";
CM_ SG_ 2332155950 I2A_Byrack_SUMDATA1_ALIV_14 "IMM发送的概要数据1的生命信号，0~15循环";
CM_ SG_ 2332155950 I2A_Byrack_VoltVld_14 "IMM采样有效标志";
CM_ SG_ 2332155950 I2A_Byrack_VoltErr_14 "IMM板电源故障标志(暂未使用）";
CM_ SG_ 2332155950 I2A_Byrack_InsResValid_14 "IMM绝缘阻值有效性";
CM_ SG_ 2332155950 Reserved_14 "预留";
CM_ SG_ 2332155950 I2A_Byrack_IsoResPos_14 "主正对机壳的有效绝缘阻值";
CM_ SG_ 2332155950 I2A_Byrack_IsoResNeg_14 "主负对机壳的有效绝缘阻值";
CM_ SG_ 2332155951 I2A_Byrack_SUMDATA1_CRC_15 "IMM发送的概要数据1的CRC";
CM_ SG_ 2332155951 I2A_Byrack_SUMDATA1_ALIV_15 "IMM发送的概要数据1的生命信号，0~15循环";
CM_ SG_ 2332155951 I2A_Byrack_VoltVld_15 "IMM采样有效标志";
CM_ SG_ 2332155951 I2A_Byrack_VoltErr_15 "IMM板电源故障标志(暂未使用）";
CM_ SG_ 2332155951 I2A_Byrack_InsResValid_15 "IMM绝缘阻值有效性";
CM_ SG_ 2332155951 Reserved_15 "预留";
CM_ SG_ 2332155951 I2A_Byrack_IsoResPos_15 "主正对机壳的有效绝缘阻值";
CM_ SG_ 2332155951 I2A_Byrack_IsoResNeg_15 "主负对机壳的有效绝缘阻值";
CM_ SG_ 2332155952 I2A_Byrack_SUMDATA1_CRC_16 "IMM发送的概要数据1的CRC";
CM_ SG_ 2332155952 I2A_Byrack_SUMDATA1_ALIV_16 "IMM发送的概要数据1的生命信号，0~15循环";
CM_ SG_ 2332155952 I2A_Byrack_VoltVld_16 "IMM采样有效标志";
CM_ SG_ 2332155952 I2A_Byrack_VoltErr_16 "IMM板电源故障标志(暂未使用）";
CM_ SG_ 2332155952 I2A_Byrack_InsResValid_16 "IMM绝缘阻值有效性";
CM_ SG_ 2332155952 Reserved_16 "预留";
CM_ SG_ 2332155952 I2A_Byrack_IsoResPos_16 "主正对机壳的有效绝缘阻值";
CM_ SG_ 2332155952 I2A_Byrack_IsoResNeg_16 "主负对机壳的有效绝缘阻值";
CM_ SG_ 2332155953 I2A_Byrack_SUMDATA1_CRC_17 "IMM发送的概要数据1的CRC";
CM_ SG_ 2332155953 I2A_Byrack_SUMDATA1_ALIV_17 "IMM发送的概要数据1的生命信号，0~15循环";
CM_ SG_ 2332155953 I2A_Byrack_VoltVld_17 "IMM采样有效标志";
CM_ SG_ 2332155953 I2A_Byrack_VoltErr_17 "IMM板电源故障标志(暂未使用）";
CM_ SG_ 2332155953 I2A_Byrack_InsResValid_17 "IMM绝缘阻值有效性";
CM_ SG_ 2332155953 Reserved_17 "预留";
CM_ SG_ 2332155953 I2A_Byrack_IsoResPos_17 "主正对机壳的有效绝缘阻值";
CM_ SG_ 2332155953 I2A_Byrack_IsoResNeg_17 "主负对机壳的有效绝缘阻值";
CM_ SG_ 2332155954 I2A_Byrack_SUMDATA1_CRC_18 "IMM发送的概要数据1的CRC";
CM_ SG_ 2332155954 I2A_Byrack_SUMDATA1_ALIV_18 "IMM发送的概要数据1的生命信号，0~15循环";
CM_ SG_ 2332155954 I2A_Byrack_VoltVld_18 "IMM采样有效标志";
CM_ SG_ 2332155954 I2A_Byrack_VoltErr_18 "IMM板电源故障标志(暂未使用）";
CM_ SG_ 2332155954 I2A_Byrack_InsResValid_18 "IMM绝缘阻值有效性";
CM_ SG_ 2332155954 Reserved_18 "预留";
CM_ SG_ 2332155954 I2A_Byrack_IsoResPos_18 "主正对机壳的有效绝缘阻值";
CM_ SG_ 2332155954 I2A_Byrack_IsoResNeg_18 "主负对机壳的有效绝缘阻值";
CM_ SG_ 2332155955 I2A_Byrack_SUMDATA1_CRC_19 "IMM发送的概要数据1的CRC";
CM_ SG_ 2332155955 I2A_Byrack_SUMDATA1_ALIV_19 "IMM发送的概要数据1的生命信号，0~15循环";
CM_ SG_ 2332155955 I2A_Byrack_VoltVld_19 "IMM采样有效标志";
CM_ SG_ 2332155955 I2A_Byrack_VoltErr_19 "IMM板电源故障标志(暂未使用）";
CM_ SG_ 2332155955 I2A_Byrack_InsResValid_19 "IMM绝缘阻值有效性";
CM_ SG_ 2332155955 Reserved_19 "预留";
CM_ SG_ 2332155955 I2A_Byrack_IsoResPos_19 "主正对机壳的有效绝缘阻值";
CM_ SG_ 2332155955 I2A_Byrack_IsoResNeg_19 "主负对机壳的有效绝缘阻值";
CM_ SG_ 2332155956 I2A_Byrack_SUMDATA1_CRC_20 "IMM发送的概要数据1的CRC";
CM_ SG_ 2332155956 I2A_Byrack_SUMDATA1_ALIV_20 "IMM发送的概要数据1的生命信号，0~15循环";
CM_ SG_ 2332155956 I2A_Byrack_VoltVld_20 "IMM采样有效标志";
CM_ SG_ 2332155956 I2A_Byrack_VoltErr_20 "IMM板电源故障标志(暂未使用）";
CM_ SG_ 2332155956 I2A_Byrack_InsResValid_20 "IMM绝缘阻值有效性";
CM_ SG_ 2332155956 Reserved_20 "预留";
CM_ SG_ 2332155956 I2A_Byrack_IsoResPos_20 "主正对机壳的有效绝缘阻值";
CM_ SG_ 2332155956 I2A_Byrack_IsoResNeg_20 "主负对机壳的有效绝缘阻值";
CM_ SG_ 2332155957 I2A_Byrack_SUMDATA1_CRC_21 "IMM发送的概要数据1的CRC";
CM_ SG_ 2332155957 I2A_Byrack_SUMDATA1_ALIV_21 "IMM发送的概要数据1的生命信号，0~15循环";
CM_ SG_ 2332155957 I2A_Byrack_VoltVld_21 "IMM采样有效标志";
CM_ SG_ 2332155957 I2A_Byrack_VoltErr_21 "IMM板电源故障标志(暂未使用）";
CM_ SG_ 2332155957 I2A_Byrack_InsResValid_21 "IMM绝缘阻值有效性";
CM_ SG_ 2332155957 Reserved_21 "预留";
CM_ SG_ 2332155957 I2A_Byrack_IsoResPos_21 "主正对机壳的有效绝缘阻值";
CM_ SG_ 2332155957 I2A_Byrack_IsoResNeg_21 "主负对机壳的有效绝缘阻值";
CM_ SG_ 2332155958 I2A_Byrack_SUMDATA1_CRC_22 "IMM发送的概要数据1的CRC";
CM_ SG_ 2332155958 I2A_Byrack_SUMDATA1_ALIV_22 "IMM发送的概要数据1的生命信号，0~15循环";
CM_ SG_ 2332155958 I2A_Byrack_VoltVld_22 "IMM采样有效标志";
CM_ SG_ 2332155958 I2A_Byrack_VoltErr_22 "IMM板电源故障标志(暂未使用）";
CM_ SG_ 2332155958 I2A_Byrack_InsResValid_22 "IMM绝缘阻值有效性";
CM_ SG_ 2332155958 Reserved_22 "预留";
CM_ SG_ 2332155958 I2A_Byrack_IsoResPos_22 "主正对机壳的有效绝缘阻值";
CM_ SG_ 2332155958 I2A_Byrack_IsoResNeg_22 "主负对机壳的有效绝缘阻值";
CM_ SG_ 2332155959 I2A_Byrack_SUMDATA1_CRC_23 "IMM发送的概要数据1的CRC";
CM_ SG_ 2332155959 I2A_Byrack_SUMDATA1_ALIV_23 "IMM发送的概要数据1的生命信号，0~15循环";
CM_ SG_ 2332155959 I2A_Byrack_VoltVld_23 "IMM采样有效标志";
CM_ SG_ 2332155959 I2A_Byrack_VoltErr_23 "IMM板电源故障标志(暂未使用）";
CM_ SG_ 2332155959 I2A_Byrack_InsResValid_23 "IMM绝缘阻值有效性";
CM_ SG_ 2332155959 Reserved_23 "预留";
CM_ SG_ 2332155959 I2A_Byrack_IsoResPos_23 "主正对机壳的有效绝缘阻值";
CM_ SG_ 2332155959 I2A_Byrack_IsoResNeg_23 "主负对机壳的有效绝缘阻值";
CM_ SG_ 2332155960 I2A_Byrack_SUMDATA1_CRC_24 "IMM发送的概要数据1的CRC";
CM_ SG_ 2332155960 I2A_Byrack_SUMDATA1_ALIV_24 "IMM发送的概要数据1的生命信号，0~15循环";
CM_ SG_ 2332155960 I2A_Byrack_VoltVld_24 "IMM采样有效标志";
CM_ SG_ 2332155960 I2A_Byrack_VoltErr_24 "IMM板电源故障标志(暂未使用）";
CM_ SG_ 2332155960 I2A_Byrack_InsResValid_24 "IMM绝缘阻值有效性";
CM_ SG_ 2332155960 Reserved_24 "预留";
CM_ SG_ 2332155960 I2A_Byrack_IsoResPos_24 "主正对机壳的有效绝缘阻值";
CM_ SG_ 2332155960 I2A_Byrack_IsoResNeg_24 "主负对机壳的有效绝缘阻值";
CM_ SG_ 2332155961 I2A_Byrack_SUMDATA1_CRC_25 "IMM发送的概要数据1的CRC";
CM_ SG_ 2332155961 I2A_Byrack_SUMDATA1_ALIV_25 "IMM发送的概要数据1的生命信号，0~15循环";
CM_ SG_ 2332155961 I2A_Byrack_VoltVld_25 "IMM采样有效标志";
CM_ SG_ 2332155961 I2A_Byrack_VoltErr_25 "IMM板电源故障标志(暂未使用）";
CM_ SG_ 2332155961 I2A_Byrack_InsResValid_25 "IMM绝缘阻值有效性";
CM_ SG_ 2332155961 Reserved_25 "预留";
CM_ SG_ 2332155961 I2A_Byrack_IsoResPos_25 "主正对机壳的有效绝缘阻值";
CM_ SG_ 2332155961 I2A_Byrack_IsoResNeg_25 "主负对机壳的有效绝缘阻值";
CM_ SG_ 2332155962 I2A_Byrack_SUMDATA1_CRC_26 "IMM发送的概要数据1的CRC";
CM_ SG_ 2332155962 I2A_Byrack_SUMDATA1_ALIV_26 "IMM发送的概要数据1的生命信号，0~15循环";
CM_ SG_ 2332155962 I2A_Byrack_VoltVld_26 "IMM采样有效标志";
CM_ SG_ 2332155962 I2A_Byrack_VoltErr_26 "IMM板电源故障标志(暂未使用）";
CM_ SG_ 2332155962 I2A_Byrack_InsResValid_26 "IMM绝缘阻值有效性";
CM_ SG_ 2332155962 Reserved_26 "预留";
CM_ SG_ 2332155962 I2A_Byrack_IsoResPos_26 "主正对机壳的有效绝缘阻值";
CM_ SG_ 2332155962 I2A_Byrack_IsoResNeg_26 "主负对机壳的有效绝缘阻值";
CM_ SG_ 2332155963 I2A_Byrack_SUMDATA1_CRC_27 "IMM发送的概要数据1的CRC";
CM_ SG_ 2332155963 I2A_Byrack_SUMDATA1_ALIV_27 "IMM发送的概要数据1的生命信号，0~15循环";
CM_ SG_ 2332155963 I2A_Byrack_VoltVld_27 "IMM采样有效标志";
CM_ SG_ 2332155963 I2A_Byrack_VoltErr_27 "IMM板电源故障标志(暂未使用）";
CM_ SG_ 2332155963 I2A_Byrack_InsResValid_27 "IMM绝缘阻值有效性";
CM_ SG_ 2332155963 Reserved_27 "预留";
CM_ SG_ 2332155963 I2A_Byrack_IsoResPos_27 "主正对机壳的有效绝缘阻值";
CM_ SG_ 2332155963 I2A_Byrack_IsoResNeg_27 "主负对机壳的有效绝缘阻值";
CM_ SG_ 2332155964 I2A_Byrack_SUMDATA1_CRC_28 "IMM发送的概要数据1的CRC";
CM_ SG_ 2332155964 I2A_Byrack_SUMDATA1_ALIV_28 "IMM发送的概要数据1的生命信号，0~15循环";
CM_ SG_ 2332155964 I2A_Byrack_VoltVld_28 "IMM采样有效标志";
CM_ SG_ 2332155964 I2A_Byrack_VoltErr_28 "IMM板电源故障标志(暂未使用）";
CM_ SG_ 2332155964 I2A_Byrack_InsResValid_28 "IMM绝缘阻值有效性";
CM_ SG_ 2332155964 Reserved_28 "预留";
CM_ SG_ 2332155964 I2A_Byrack_IsoResPos_28 "主正对机壳的有效绝缘阻值";
CM_ SG_ 2332155964 I2A_Byrack_IsoResNeg_28 "主负对机壳的有效绝缘阻值";
CM_ SG_ 2332155965 I2A_Byrack_SUMDATA1_CRC_29 "IMM发送的概要数据1的CRC";
CM_ SG_ 2332155965 I2A_Byrack_SUMDATA1_ALIV_29 "IMM发送的概要数据1的生命信号，0~15循环";
CM_ SG_ 2332155965 I2A_Byrack_VoltVld_29 "IMM采样有效标志";
CM_ SG_ 2332155965 I2A_Byrack_VoltErr_29 "IMM板电源故障标志(暂未使用）";
CM_ SG_ 2332155965 I2A_Byrack_InsResValid_29 "IMM绝缘阻值有效性";
CM_ SG_ 2332155965 Reserved_29 "预留";
CM_ SG_ 2332155965 I2A_Byrack_IsoResPos_29 "主正对机壳的有效绝缘阻值";
CM_ SG_ 2332155965 I2A_Byrack_IsoResNeg_29 "主负对机壳的有效绝缘阻值";
CM_ SG_ 2332155966 I2A_Byrack_SUMDATA1_CRC_30 "IMM发送的概要数据1的CRC";
CM_ SG_ 2332155966 I2A_Byrack_SUMDATA1_ALIV_30 "IMM发送的概要数据1的生命信号，0~15循环";
CM_ SG_ 2332155966 I2A_Byrack_VoltVld_30 "IMM采样有效标志";
CM_ SG_ 2332155966 I2A_Byrack_VoltErr_30 "IMM板电源故障标志(暂未使用）";
CM_ SG_ 2332155966 I2A_Byrack_InsResValid_30 "IMM绝缘阻值有效性";
CM_ SG_ 2332155966 Reserved_30 "预留";
CM_ SG_ 2332155966 I2A_Byrack_IsoResPos_30 "主正对机壳的有效绝缘阻值";
CM_ SG_ 2332155966 I2A_Byrack_IsoResNeg_30 "主负对机壳的有效绝缘阻值";
CM_ SG_ 2332155967 I2A_Byrack_SUMDATA1_CRC_31 "IMM发送的概要数据1的CRC";
CM_ SG_ 2332155967 I2A_Byrack_SUMDATA1_ALIV_31 "IMM发送的概要数据1的生命信号，0~15循环";
CM_ SG_ 2332155967 I2A_Byrack_VoltVld_31 "IMM采样有效标志";
CM_ SG_ 2332155967 I2A_Byrack_VoltErr_31 "IMM板电源故障标志(暂未使用）";
CM_ SG_ 2332155967 I2A_Byrack_InsResValid_31 "IMM绝缘阻值有效性";
CM_ SG_ 2332155967 Reserved_31 "预留";
CM_ SG_ 2332155967 I2A_Byrack_IsoResPos_31 "主正对机壳的有效绝缘阻值";
CM_ SG_ 2332155967 I2A_Byrack_IsoResNeg_31 "主负对机壳的有效绝缘阻值";
CM_ SG_ 2332107153 CRC_M2I_Byrack_IMM1_01 "CRC校验_IMM1";
CM_ SG_ 2332107153 M2I_Byrack_HVS_IMM1_01 "绝缘测量电压_IMM1";
CM_ SG_ 2332107153 M2I_Byrack_Enable_IMM1_01 "绝缘采样使能位_IMM1";
CM_ SG_ 2332107153 M2I_Byrack_ReVeEnable_IMM1_01 "读取软件版本使能位__IMM1";
CM_ SG_ 2332107153 Reserved_01 "预留预留";
CM_ SG_ 2332107153 M2I_Byrack_IsPostTm_IMM1_01 "绝缘采样时间_IMM1";
CM_ SG_ 2332107153 M2I_Byrack_SysABStTm_IMM1_01 "电压稳定时间_IMM1";
CM_ SG_ 2332107154 CRC_M2I_Byrack_IMM1_02 "CRC校验_IMM1";
CM_ SG_ 2332107154 M2I_Byrack_HVS_IMM1_02 "绝缘测量电压_IMM1";
CM_ SG_ 2332107154 M2I_Byrack_Enable_IMM1_02 "绝缘采样使能位_IMM1";
CM_ SG_ 2332107154 M2I_Byrack_ReVeEnable_IMM1_02 "读取软件版本使能位__IMM1";
CM_ SG_ 2332107154 Reserved_02 "预留预留";
CM_ SG_ 2332107154 M2I_Byrack_IsPostTm_IMM1_02 "绝缘采样时间_IMM1";
CM_ SG_ 2332107154 M2I_Byrack_SysABStTm_IMM1_02 "电压稳定时间_IMM1";
CM_ SG_ 2332107155 CRC_M2I_Byrack_IMM1_03 "CRC校验_IMM1";
CM_ SG_ 2332107155 M2I_Byrack_HVS_IMM1_03 "绝缘测量电压_IMM1";
CM_ SG_ 2332107155 M2I_Byrack_Enable_IMM1_03 "绝缘采样使能位_IMM1";
CM_ SG_ 2332107155 M2I_Byrack_ReVeEnable_IMM1_03 "读取软件版本使能位__IMM1";
CM_ SG_ 2332107155 Reserved_03 "预留预留";
CM_ SG_ 2332107155 M2I_Byrack_IsPostTm_IMM1_03 "绝缘采样时间_IMM1";
CM_ SG_ 2332107155 M2I_Byrack_SysABStTm_IMM1_03 "电压稳定时间_IMM1";
CM_ SG_ 2332107156 CRC_M2I_Byrack_IMM1_04 "CRC校验_IMM1";
CM_ SG_ 2332107156 M2I_Byrack_HVS_IMM1_04 "绝缘测量电压_IMM1";
CM_ SG_ 2332107156 M2I_Byrack_Enable_IMM1_04 "绝缘采样使能位_IMM1";
CM_ SG_ 2332107156 M2I_Byrack_ReVeEnable_IMM1_04 "读取软件版本使能位__IMM1";
CM_ SG_ 2332107156 Reserved_04 "预留预留";
CM_ SG_ 2332107156 M2I_Byrack_IsPostTm_IMM1_04 "绝缘采样时间_IMM1";
CM_ SG_ 2332107156 M2I_Byrack_SysABStTm_IMM1_04 "电压稳定时间_IMM1";
CM_ SG_ 2332107157 CRC_M2I_Byrack_IMM1_05 "CRC校验_IMM1";
CM_ SG_ 2332107157 M2I_Byrack_HVS_IMM1_05 "绝缘测量电压_IMM1";
CM_ SG_ 2332107157 M2I_Byrack_Enable_IMM1_05 "绝缘采样使能位_IMM1";
CM_ SG_ 2332107157 M2I_Byrack_ReVeEnable_IMM1_05 "读取软件版本使能位__IMM1";
CM_ SG_ 2332107157 Reserved_05 "预留预留";
CM_ SG_ 2332107157 M2I_Byrack_IsPostTm_IMM1_05 "绝缘采样时间_IMM1";
CM_ SG_ 2332107157 M2I_Byrack_SysABStTm_IMM1_05 "电压稳定时间_IMM1";
CM_ SG_ 2332107158 CRC_M2I_Byrack_IMM1_06 "CRC校验_IMM1";
CM_ SG_ 2332107158 M2I_Byrack_HVS_IMM1_06 "绝缘测量电压_IMM1";
CM_ SG_ 2332107158 M2I_Byrack_Enable_IMM1_06 "绝缘采样使能位_IMM1";
CM_ SG_ 2332107158 M2I_Byrack_ReVeEnable_IMM1_06 "读取软件版本使能位__IMM1";
CM_ SG_ 2332107158 Reserved_06 "预留预留";
CM_ SG_ 2332107158 M2I_Byrack_IsPostTm_IMM1_06 "绝缘采样时间_IMM1";
CM_ SG_ 2332107158 M2I_Byrack_SysABStTm_IMM1_06 "电压稳定时间_IMM1";
CM_ SG_ 2332107159 CRC_M2I_Byrack_IMM1_07 "CRC校验_IMM1";
CM_ SG_ 2332107159 M2I_Byrack_HVS_IMM1_07 "绝缘测量电压_IMM1";
CM_ SG_ 2332107159 M2I_Byrack_Enable_IMM1_07 "绝缘采样使能位_IMM1";
CM_ SG_ 2332107159 M2I_Byrack_ReVeEnable_IMM1_07 "读取软件版本使能位__IMM1";
CM_ SG_ 2332107159 Reserved_07 "预留预留";
CM_ SG_ 2332107159 M2I_Byrack_IsPostTm_IMM1_07 "绝缘采样时间_IMM1";
CM_ SG_ 2332107159 M2I_Byrack_SysABStTm_IMM1_07 "电压稳定时间_IMM1";
CM_ SG_ 2332107160 CRC_M2I_Byrack_IMM1_08 "CRC校验_IMM1";
CM_ SG_ 2332107160 M2I_Byrack_HVS_IMM1_08 "绝缘测量电压_IMM1";
CM_ SG_ 2332107160 M2I_Byrack_Enable_IMM1_08 "绝缘采样使能位_IMM1";
CM_ SG_ 2332107160 M2I_Byrack_ReVeEnable_IMM1_08 "读取软件版本使能位__IMM1";
CM_ SG_ 2332107160 Reserved_08 "预留预留";
CM_ SG_ 2332107160 M2I_Byrack_IsPostTm_IMM1_08 "绝缘采样时间_IMM1";
CM_ SG_ 2332107160 M2I_Byrack_SysABStTm_IMM1_08 "电压稳定时间_IMM1";
CM_ SG_ 2332107161 CRC_M2I_Byrack_IMM1_09 "CRC校验_IMM1";
CM_ SG_ 2332107161 M2I_Byrack_HVS_IMM1_09 "绝缘测量电压_IMM1";
CM_ SG_ 2332107161 M2I_Byrack_Enable_IMM1_09 "绝缘采样使能位_IMM1";
CM_ SG_ 2332107161 M2I_Byrack_ReVeEnable_IMM1_09 "读取软件版本使能位__IMM1";
CM_ SG_ 2332107161 Reserved_09 "预留预留";
CM_ SG_ 2332107161 M2I_Byrack_IsPostTm_IMM1_09 "绝缘采样时间_IMM1";
CM_ SG_ 2332107161 M2I_Byrack_SysABStTm_IMM1_09 "电压稳定时间_IMM1";
CM_ SG_ 2332107162 CRC_M2I_Byrack_IMM1_10 "CRC校验_IMM1";
CM_ SG_ 2332107162 M2I_Byrack_HVS_IMM1_10 "绝缘测量电压_IMM1";
CM_ SG_ 2332107162 M2I_Byrack_Enable_IMM1_10 "绝缘采样使能位_IMM1";
CM_ SG_ 2332107162 M2I_Byrack_ReVeEnable_IMM1_10 "读取软件版本使能位__IMM1";
CM_ SG_ 2332107162 Reserved_10 "预留预留";
CM_ SG_ 2332107162 M2I_Byrack_IsPostTm_IMM1_10 "绝缘采样时间_IMM1";
CM_ SG_ 2332107162 M2I_Byrack_SysABStTm_IMM1_10 "电压稳定时间_IMM1";
CM_ SG_ 2332107163 CRC_M2I_Byrack_IMM1_11 "CRC校验_IMM1";
CM_ SG_ 2332107163 M2I_Byrack_HVS_IMM1_11 "绝缘测量电压_IMM1";
CM_ SG_ 2332107163 M2I_Byrack_Enable_IMM1_11 "绝缘采样使能位_IMM1";
CM_ SG_ 2332107163 M2I_Byrack_ReVeEnable_IMM1_11 "读取软件版本使能位__IMM1";
CM_ SG_ 2332107163 Reserved_11 "预留预留";
CM_ SG_ 2332107163 M2I_Byrack_IsPostTm_IMM1_11 "绝缘采样时间_IMM1";
CM_ SG_ 2332107163 M2I_Byrack_SysABStTm_IMM1_11 "电压稳定时间_IMM1";
CM_ SG_ 2332107164 CRC_M2I_Byrack_IMM1_12 "CRC校验_IMM1";
CM_ SG_ 2332107164 M2I_Byrack_HVS_IMM1_12 "绝缘测量电压_IMM1";
CM_ SG_ 2332107164 M2I_Byrack_Enable_IMM1_12 "绝缘采样使能位_IMM1";
CM_ SG_ 2332107164 M2I_Byrack_ReVeEnable_IMM1_12 "读取软件版本使能位__IMM1";
CM_ SG_ 2332107164 Reserved_12 "预留预留";
CM_ SG_ 2332107164 M2I_Byrack_IsPostTm_IMM1_12 "绝缘采样时间_IMM1";
CM_ SG_ 2332107164 M2I_Byrack_SysABStTm_IMM1_12 "电压稳定时间_IMM1";
CM_ SG_ 2332107165 CRC_M2I_Byrack_IMM1_13 "CRC校验_IMM1";
CM_ SG_ 2332107165 M2I_Byrack_HVS_IMM1_13 "绝缘测量电压_IMM1";
CM_ SG_ 2332107165 M2I_Byrack_Enable_IMM1_13 "绝缘采样使能位_IMM1";
CM_ SG_ 2332107165 M2I_Byrack_ReVeEnable_IMM1_13 "读取软件版本使能位__IMM1";
CM_ SG_ 2332107165 Reserved_13 "预留预留";
CM_ SG_ 2332107165 M2I_Byrack_IsPostTm_IMM1_13 "绝缘采样时间_IMM1";
CM_ SG_ 2332107165 M2I_Byrack_SysABStTm_IMM1_13 "电压稳定时间_IMM1";
CM_ SG_ 2332107166 CRC_M2I_Byrack_IMM1_14 "CRC校验_IMM1";
CM_ SG_ 2332107166 M2I_Byrack_HVS_IMM1_14 "绝缘测量电压_IMM1";
CM_ SG_ 2332107166 M2I_Byrack_Enable_IMM1_14 "绝缘采样使能位_IMM1";
CM_ SG_ 2332107166 M2I_Byrack_ReVeEnable_IMM1_14 "读取软件版本使能位__IMM1";
CM_ SG_ 2332107166 Reserved_14 "预留预留";
CM_ SG_ 2332107166 M2I_Byrack_IsPostTm_IMM1_14 "绝缘采样时间_IMM1";
CM_ SG_ 2332107166 M2I_Byrack_SysABStTm_IMM1_14 "电压稳定时间_IMM1";
CM_ SG_ 2332107167 CRC_M2I_Byrack_IMM1_15 "CRC校验_IMM1";
CM_ SG_ 2332107167 M2I_Byrack_HVS_IMM1_15 "绝缘测量电压_IMM1";
CM_ SG_ 2332107167 M2I_Byrack_Enable_IMM1_15 "绝缘采样使能位_IMM1";
CM_ SG_ 2332107167 M2I_Byrack_ReVeEnable_IMM1_15 "读取软件版本使能位__IMM1";
CM_ SG_ 2332107167 Reserved_15 "预留预留";
CM_ SG_ 2332107167 M2I_Byrack_IsPostTm_IMM1_15 "绝缘采样时间_IMM1";
CM_ SG_ 2332107167 M2I_Byrack_SysABStTm_IMM1_15 "电压稳定时间_IMM1";
CM_ SG_ 2332107168 CRC_M2I_Byrack_IMM1_16 "CRC校验_IMM1";
CM_ SG_ 2332107168 M2I_Byrack_HVS_IMM1_16 "绝缘测量电压_IMM1";
CM_ SG_ 2332107168 M2I_Byrack_Enable_IMM1_16 "绝缘采样使能位_IMM1";
CM_ SG_ 2332107168 M2I_Byrack_ReVeEnable_IMM1_16 "读取软件版本使能位__IMM1";
CM_ SG_ 2332107168 Reserved_16 "预留预留";
CM_ SG_ 2332107168 M2I_Byrack_IsPostTm_IMM1_16 "绝缘采样时间_IMM1";
CM_ SG_ 2332107168 M2I_Byrack_SysABStTm_IMM1_16 "电压稳定时间_IMM1";
CM_ SG_ 2332107169 CRC_M2I_Byrack_IMM1_17 "CRC校验_IMM1";
CM_ SG_ 2332107169 M2I_Byrack_HVS_IMM1_17 "绝缘测量电压_IMM1";
CM_ SG_ 2332107169 M2I_Byrack_Enable_IMM1_17 "绝缘采样使能位_IMM1";
CM_ SG_ 2332107169 M2I_Byrack_ReVeEnable_IMM1_17 "读取软件版本使能位__IMM1";
CM_ SG_ 2332107169 Reserved_17 "预留预留";
CM_ SG_ 2332107169 M2I_Byrack_IsPostTm_IMM1_17 "绝缘采样时间_IMM1";
CM_ SG_ 2332107169 M2I_Byrack_SysABStTm_IMM1_17 "电压稳定时间_IMM1";
CM_ SG_ 2332107170 CRC_M2I_Byrack_IMM1_18 "CRC校验_IMM1";
CM_ SG_ 2332107170 M2I_Byrack_HVS_IMM1_18 "绝缘测量电压_IMM1";
CM_ SG_ 2332107170 M2I_Byrack_Enable_IMM1_18 "绝缘采样使能位_IMM1";
CM_ SG_ 2332107170 M2I_Byrack_ReVeEnable_IMM1_18 "读取软件版本使能位__IMM1";
CM_ SG_ 2332107170 Reserved_18 "预留预留";
CM_ SG_ 2332107170 M2I_Byrack_IsPostTm_IMM1_18 "绝缘采样时间_IMM1";
CM_ SG_ 2332107170 M2I_Byrack_SysABStTm_IMM1_18 "电压稳定时间_IMM1";
CM_ SG_ 2332107171 CRC_M2I_Byrack_IMM1_19 "CRC校验_IMM1";
CM_ SG_ 2332107171 M2I_Byrack_HVS_IMM1_19 "绝缘测量电压_IMM1";
CM_ SG_ 2332107171 M2I_Byrack_Enable_IMM1_19 "绝缘采样使能位_IMM1";
CM_ SG_ 2332107171 M2I_Byrack_ReVeEnable_IMM1_19 "读取软件版本使能位__IMM1";
CM_ SG_ 2332107171 Reserved_19 "预留预留";
CM_ SG_ 2332107171 M2I_Byrack_IsPostTm_IMM1_19 "绝缘采样时间_IMM1";
CM_ SG_ 2332107171 M2I_Byrack_SysABStTm_IMM1_19 "电压稳定时间_IMM1";
CM_ SG_ 2332107172 CRC_M2I_Byrack_IMM1_20 "CRC校验_IMM1";
CM_ SG_ 2332107172 M2I_Byrack_HVS_IMM1_20 "绝缘测量电压_IMM1";
CM_ SG_ 2332107172 M2I_Byrack_Enable_IMM1_20 "绝缘采样使能位_IMM1";
CM_ SG_ 2332107172 M2I_Byrack_ReVeEnable_IMM1_20 "读取软件版本使能位__IMM1";
CM_ SG_ 2332107172 Reserved_20 "预留预留";
CM_ SG_ 2332107172 M2I_Byrack_IsPostTm_IMM1_20 "绝缘采样时间_IMM1";
CM_ SG_ 2332107172 M2I_Byrack_SysABStTm_IMM1_20 "电压稳定时间_IMM1";
CM_ SG_ 2332107173 CRC_M2I_Byrack_IMM1_21 "CRC校验_IMM1";
CM_ SG_ 2332107173 M2I_Byrack_HVS_IMM1_21 "绝缘测量电压_IMM1";
CM_ SG_ 2332107173 M2I_Byrack_Enable_IMM1_21 "绝缘采样使能位_IMM1";
CM_ SG_ 2332107173 M2I_Byrack_ReVeEnable_IMM1_21 "读取软件版本使能位__IMM1";
CM_ SG_ 2332107173 Reserved_21 "预留预留";
CM_ SG_ 2332107173 M2I_Byrack_IsPostTm_IMM1_21 "绝缘采样时间_IMM1";
CM_ SG_ 2332107173 M2I_Byrack_SysABStTm_IMM1_21 "电压稳定时间_IMM1";
CM_ SG_ 2332107174 CRC_M2I_Byrack_IMM1_22 "CRC校验_IMM1";
CM_ SG_ 2332107174 M2I_Byrack_HVS_IMM1_22 "绝缘测量电压_IMM1";
CM_ SG_ 2332107174 M2I_Byrack_Enable_IMM1_22 "绝缘采样使能位_IMM1";
CM_ SG_ 2332107174 M2I_Byrack_ReVeEnable_IMM1_22 "读取软件版本使能位__IMM1";
CM_ SG_ 2332107174 Reserved_22 "预留预留";
CM_ SG_ 2332107174 M2I_Byrack_IsPostTm_IMM1_22 "绝缘采样时间_IMM1";
CM_ SG_ 2332107174 M2I_Byrack_SysABStTm_IMM1_22 "电压稳定时间_IMM1";
CM_ SG_ 2332107175 CRC_M2I_Byrack_IMM1_23 "CRC校验_IMM1";
CM_ SG_ 2332107175 M2I_Byrack_HVS_IMM1_23 "绝缘测量电压_IMM1";
CM_ SG_ 2332107175 M2I_Byrack_Enable_IMM1_23 "绝缘采样使能位_IMM1";
CM_ SG_ 2332107175 M2I_Byrack_ReVeEnable_IMM1_23 "读取软件版本使能位__IMM1";
CM_ SG_ 2332107175 Reserved_23 "预留预留";
CM_ SG_ 2332107175 M2I_Byrack_IsPostTm_IMM1_23 "绝缘采样时间_IMM1";
CM_ SG_ 2332107175 M2I_Byrack_SysABStTm_IMM1_23 "电压稳定时间_IMM1";
CM_ SG_ 2332107176 CRC_M2I_Byrack_IMM1_24 "CRC校验_IMM1";
CM_ SG_ 2332107176 M2I_Byrack_HVS_IMM1_24 "绝缘测量电压_IMM1";
CM_ SG_ 2332107176 M2I_Byrack_Enable_IMM1_24 "绝缘采样使能位_IMM1";
CM_ SG_ 2332107176 M2I_Byrack_ReVeEnable_IMM1_24 "读取软件版本使能位__IMM1";
CM_ SG_ 2332107176 Reserved_24 "预留预留";
CM_ SG_ 2332107176 M2I_Byrack_IsPostTm_IMM1_24 "绝缘采样时间_IMM1";
CM_ SG_ 2332107176 M2I_Byrack_SysABStTm_IMM1_24 "电压稳定时间_IMM1";
CM_ SG_ 2332107177 CRC_M2I_Byrack_IMM1_25 "CRC校验_IMM1";
CM_ SG_ 2332107177 M2I_Byrack_HVS_IMM1_25 "绝缘测量电压_IMM1";
CM_ SG_ 2332107177 M2I_Byrack_Enable_IMM1_25 "绝缘采样使能位_IMM1";
CM_ SG_ 2332107177 M2I_Byrack_ReVeEnable_IMM1_25 "读取软件版本使能位__IMM1";
CM_ SG_ 2332107177 Reserved_25 "预留预留";
CM_ SG_ 2332107177 M2I_Byrack_IsPostTm_IMM1_25 "绝缘采样时间_IMM1";
CM_ SG_ 2332107177 M2I_Byrack_SysABStTm_IMM1_25 "电压稳定时间_IMM1";
CM_ SG_ 2332107178 CRC_M2I_Byrack_IMM1_26 "CRC校验_IMM1";
CM_ SG_ 2332107178 M2I_Byrack_HVS_IMM1_26 "绝缘测量电压_IMM1";
CM_ SG_ 2332107178 M2I_Byrack_Enable_IMM1_26 "绝缘采样使能位_IMM1";
CM_ SG_ 2332107178 M2I_Byrack_ReVeEnable_IMM1_26 "读取软件版本使能位__IMM1";
CM_ SG_ 2332107178 Reserved_26 "预留预留";
CM_ SG_ 2332107178 M2I_Byrack_IsPostTm_IMM1_26 "绝缘采样时间_IMM1";
CM_ SG_ 2332107178 M2I_Byrack_SysABStTm_IMM1_26 "电压稳定时间_IMM1";
CM_ SG_ 2332107179 CRC_M2I_Byrack_IMM1_27 "CRC校验_IMM1";
CM_ SG_ 2332107179 M2I_Byrack_HVS_IMM1_27 "绝缘测量电压_IMM1";
CM_ SG_ 2332107179 M2I_Byrack_Enable_IMM1_27 "绝缘采样使能位_IMM1";
CM_ SG_ 2332107179 M2I_Byrack_ReVeEnable_IMM1_27 "读取软件版本使能位__IMM1";
CM_ SG_ 2332107179 Reserved_27 "预留预留";
CM_ SG_ 2332107179 M2I_Byrack_IsPostTm_IMM1_27 "绝缘采样时间_IMM1";
CM_ SG_ 2332107179 M2I_Byrack_SysABStTm_IMM1_27 "电压稳定时间_IMM1";
CM_ SG_ 2332107180 CRC_M2I_Byrack_IMM1_28 "CRC校验_IMM1";
CM_ SG_ 2332107180 M2I_Byrack_HVS_IMM1_28 "绝缘测量电压_IMM1";
CM_ SG_ 2332107180 M2I_Byrack_Enable_IMM1_28 "绝缘采样使能位_IMM1";
CM_ SG_ 2332107180 M2I_Byrack_ReVeEnable_IMM1_28 "读取软件版本使能位__IMM1";
CM_ SG_ 2332107180 Reserved_28 "预留预留";
CM_ SG_ 2332107180 M2I_Byrack_IsPostTm_IMM1_28 "绝缘采样时间_IMM1";
CM_ SG_ 2332107180 M2I_Byrack_SysABStTm_IMM1_28 "电压稳定时间_IMM1";
CM_ SG_ 2332107181 CRC_M2I_Byrack_IMM1_29 "CRC校验_IMM1";
CM_ SG_ 2332107181 M2I_Byrack_HVS_IMM1_29 "绝缘测量电压_IMM1";
CM_ SG_ 2332107181 M2I_Byrack_Enable_IMM1_29 "绝缘采样使能位_IMM1";
CM_ SG_ 2332107181 M2I_Byrack_ReVeEnable_IMM1_29 "读取软件版本使能位__IMM1";
CM_ SG_ 2332107181 Reserved_29 "预留预留";
CM_ SG_ 2332107181 M2I_Byrack_IsPostTm_IMM1_29 "绝缘采样时间_IMM1";
CM_ SG_ 2332107181 M2I_Byrack_SysABStTm_IMM1_29 "电压稳定时间_IMM1";
CM_ SG_ 2332107182 CRC_M2I_Byrack_IMM1_30 "CRC校验_IMM1";
CM_ SG_ 2332107182 M2I_Byrack_HVS_IMM1_30 "绝缘测量电压_IMM1";
CM_ SG_ 2332107182 M2I_Byrack_Enable_IMM1_30 "绝缘采样使能位_IMM1";
CM_ SG_ 2332107182 M2I_Byrack_ReVeEnable_IMM1_30 "读取软件版本使能位__IMM1";
CM_ SG_ 2332107182 Reserved_30 "预留预留";
CM_ SG_ 2332107182 M2I_Byrack_IsPostTm_IMM1_30 "绝缘采样时间_IMM1";
CM_ SG_ 2332107182 M2I_Byrack_SysABStTm_IMM1_30 "电压稳定时间_IMM1";
CM_ SG_ 2332107183 CRC_M2I_Byrack_IMM1_31 "CRC校验_IMM1";
CM_ SG_ 2332107183 M2I_Byrack_HVS_IMM1_31 "绝缘测量电压_IMM1";
CM_ SG_ 2332107183 M2I_Byrack_Enable_IMM1_31 "绝缘采样使能位_IMM1";
CM_ SG_ 2332107183 M2I_Byrack_ReVeEnable_IMM1_31 "读取软件版本使能位__IMM1";
CM_ SG_ 2332107183 Reserved_31 "预留预留";
CM_ SG_ 2332107183 M2I_Byrack_IsPostTm_IMM1_31 "绝缘采样时间_IMM1";
CM_ SG_ 2332107183 M2I_Byrack_SysABStTm_IMM1_31 "电压稳定时间_IMM1";
CM_ SG_ 2332107409 CRC_M2I_Byrack_IMM2_01 "CRC校验_IMM2";
CM_ SG_ 2332107409 M2I_Byrack_HVS_IMM2_01 "绝缘测量电压_IMM2";
CM_ SG_ 2332107409 M2I_Byrack_Enable_IMM2_01 "绝缘采样使能位_IMM2";
CM_ SG_ 2332107409 M2I_Byrack_ReVeEnable_IMM2_01 "读取软件版本使能位_IMM2";
CM_ SG_ 2332107409 Reserved_01 "预留预留";
CM_ SG_ 2332107409 M2I_Byrack_IsPostTm_IMM2_01 "绝缘采样时间_IMM2";
CM_ SG_ 2332107409 M2I_Byrack_SysABStTm_IMM2_01 "电压稳定时间_IMM2";
CM_ SG_ 2332107410 CRC_M2I_Byrack_IMM2_02 "CRC校验_IMM2";
CM_ SG_ 2332107410 M2I_Byrack_HVS_IMM2_02 "绝缘测量电压_IMM2";
CM_ SG_ 2332107410 M2I_Byrack_Enable_IMM2_02 "绝缘采样使能位_IMM2";
CM_ SG_ 2332107410 M2I_Byrack_ReVeEnable_IMM2_02 "读取软件版本使能位_IMM2";
CM_ SG_ 2332107410 Reserved_02 "预留预留";
CM_ SG_ 2332107410 M2I_Byrack_IsPostTm_IMM2_02 "绝缘采样时间_IMM2";
CM_ SG_ 2332107410 M2I_Byrack_SysABStTm_IMM2_02 "电压稳定时间_IMM2";
CM_ SG_ 2332107411 CRC_M2I_Byrack_IMM2_03 "CRC校验_IMM2";
CM_ SG_ 2332107411 M2I_Byrack_HVS_IMM2_03 "绝缘测量电压_IMM2";
CM_ SG_ 2332107411 M2I_Byrack_Enable_IMM2_03 "绝缘采样使能位_IMM2";
CM_ SG_ 2332107411 M2I_Byrack_ReVeEnable_IMM2_03 "读取软件版本使能位_IMM2";
CM_ SG_ 2332107411 Reserved_03 "预留预留";
CM_ SG_ 2332107411 M2I_Byrack_IsPostTm_IMM2_03 "绝缘采样时间_IMM2";
CM_ SG_ 2332107411 M2I_Byrack_SysABStTm_IMM2_03 "电压稳定时间_IMM2";
CM_ SG_ 2332107412 CRC_M2I_Byrack_IMM2_04 "CRC校验_IMM2";
CM_ SG_ 2332107412 M2I_Byrack_HVS_IMM2_04 "绝缘测量电压_IMM2";
CM_ SG_ 2332107412 M2I_Byrack_Enable_IMM2_04 "绝缘采样使能位_IMM2";
CM_ SG_ 2332107412 M2I_Byrack_ReVeEnable_IMM2_04 "读取软件版本使能位_IMM2";
CM_ SG_ 2332107412 Reserved_04 "预留预留";
CM_ SG_ 2332107412 M2I_Byrack_IsPostTm_IMM2_04 "绝缘采样时间_IMM2";
CM_ SG_ 2332107412 M2I_Byrack_SysABStTm_IMM2_04 "电压稳定时间_IMM2";
CM_ SG_ 2332107413 CRC_M2I_Byrack_IMM2_05 "CRC校验_IMM2";
CM_ SG_ 2332107413 M2I_Byrack_HVS_IMM2_05 "绝缘测量电压_IMM2";
CM_ SG_ 2332107413 M2I_Byrack_Enable_IMM2_05 "绝缘采样使能位_IMM2";
CM_ SG_ 2332107413 M2I_Byrack_ReVeEnable_IMM2_05 "读取软件版本使能位_IMM2";
CM_ SG_ 2332107413 Reserved_05 "预留预留";
CM_ SG_ 2332107413 M2I_Byrack_IsPostTm_IMM2_05 "绝缘采样时间_IMM2";
CM_ SG_ 2332107413 M2I_Byrack_SysABStTm_IMM2_05 "电压稳定时间_IMM2";
CM_ SG_ 2332107414 CRC_M2I_Byrack_IMM2_06 "CRC校验_IMM2";
CM_ SG_ 2332107414 M2I_Byrack_HVS_IMM2_06 "绝缘测量电压_IMM2";
CM_ SG_ 2332107414 M2I_Byrack_Enable_IMM2_06 "绝缘采样使能位_IMM2";
CM_ SG_ 2332107414 M2I_Byrack_ReVeEnable_IMM2_06 "读取软件版本使能位_IMM2";
CM_ SG_ 2332107414 Reserved_06 "预留预留";
CM_ SG_ 2332107414 M2I_Byrack_IsPostTm_IMM2_06 "绝缘采样时间_IMM2";
CM_ SG_ 2332107414 M2I_Byrack_SysABStTm_IMM2_06 "电压稳定时间_IMM2";
CM_ SG_ 2332107415 CRC_M2I_Byrack_IMM2_07 "CRC校验_IMM2";
CM_ SG_ 2332107415 M2I_Byrack_HVS_IMM2_07 "绝缘测量电压_IMM2";
CM_ SG_ 2332107415 M2I_Byrack_Enable_IMM2_07 "绝缘采样使能位_IMM2";
CM_ SG_ 2332107415 M2I_Byrack_ReVeEnable_IMM2_07 "读取软件版本使能位_IMM2";
CM_ SG_ 2332107415 Reserved_07 "预留预留";
CM_ SG_ 2332107415 M2I_Byrack_IsPostTm_IMM2_07 "绝缘采样时间_IMM2";
CM_ SG_ 2332107415 M2I_Byrack_SysABStTm_IMM2_07 "电压稳定时间_IMM2";
CM_ SG_ 2332107416 CRC_M2I_Byrack_IMM2_08 "CRC校验_IMM2";
CM_ SG_ 2332107416 M2I_Byrack_HVS_IMM2_08 "绝缘测量电压_IMM2";
CM_ SG_ 2332107416 M2I_Byrack_Enable_IMM2_08 "绝缘采样使能位_IMM2";
CM_ SG_ 2332107416 M2I_Byrack_ReVeEnable_IMM2_08 "读取软件版本使能位_IMM2";
CM_ SG_ 2332107416 Reserved_08 "预留预留";
CM_ SG_ 2332107416 M2I_Byrack_IsPostTm_IMM2_08 "绝缘采样时间_IMM2";
CM_ SG_ 2332107416 M2I_Byrack_SysABStTm_IMM2_08 "电压稳定时间_IMM2";
CM_ SG_ 2332107417 CRC_M2I_Byrack_IMM2_09 "CRC校验_IMM2";
CM_ SG_ 2332107417 M2I_Byrack_HVS_IMM2_09 "绝缘测量电压_IMM2";
CM_ SG_ 2332107417 M2I_Byrack_Enable_IMM2_09 "绝缘采样使能位_IMM2";
CM_ SG_ 2332107417 M2I_Byrack_ReVeEnable_IMM2_09 "读取软件版本使能位_IMM2";
CM_ SG_ 2332107417 Reserved_09 "预留预留";
CM_ SG_ 2332107417 M2I_Byrack_IsPostTm_IMM2_09 "绝缘采样时间_IMM2";
CM_ SG_ 2332107417 M2I_Byrack_SysABStTm_IMM2_09 "电压稳定时间_IMM2";
CM_ SG_ 2332107418 CRC_M2I_Byrack_IMM2_10 "CRC校验_IMM2";
CM_ SG_ 2332107418 M2I_Byrack_HVS_IMM2_10 "绝缘测量电压_IMM2";
CM_ SG_ 2332107418 M2I_Byrack_Enable_IMM2_10 "绝缘采样使能位_IMM2";
CM_ SG_ 2332107418 M2I_Byrack_ReVeEnable_IMM2_10 "读取软件版本使能位_IMM2";
CM_ SG_ 2332107418 Reserved_10 "预留预留";
CM_ SG_ 2332107418 M2I_Byrack_IsPostTm_IMM2_10 "绝缘采样时间_IMM2";
CM_ SG_ 2332107418 M2I_Byrack_SysABStTm_IMM2_10 "电压稳定时间_IMM2";
CM_ SG_ 2332107419 CRC_M2I_Byrack_IMM2_11 "CRC校验_IMM2";
CM_ SG_ 2332107419 M2I_Byrack_HVS_IMM2_11 "绝缘测量电压_IMM2";
CM_ SG_ 2332107419 M2I_Byrack_Enable_IMM2_11 "绝缘采样使能位_IMM2";
CM_ SG_ 2332107419 M2I_Byrack_ReVeEnable_IMM2_11 "读取软件版本使能位_IMM2";
CM_ SG_ 2332107419 Reserved_11 "预留预留";
CM_ SG_ 2332107419 M2I_Byrack_IsPostTm_IMM2_11 "绝缘采样时间_IMM2";
CM_ SG_ 2332107419 M2I_Byrack_SysABStTm_IMM2_11 "电压稳定时间_IMM2";
CM_ SG_ 2332107420 CRC_M2I_Byrack_IMM2_12 "CRC校验_IMM2";
CM_ SG_ 2332107420 M2I_Byrack_HVS_IMM2_12 "绝缘测量电压_IMM2";
CM_ SG_ 2332107420 M2I_Byrack_Enable_IMM2_12 "绝缘采样使能位_IMM2";
CM_ SG_ 2332107420 M2I_Byrack_ReVeEnable_IMM2_12 "读取软件版本使能位_IMM2";
CM_ SG_ 2332107420 Reserved_12 "预留预留";
CM_ SG_ 2332107420 M2I_Byrack_IsPostTm_IMM2_12 "绝缘采样时间_IMM2";
CM_ SG_ 2332107420 M2I_Byrack_SysABStTm_IMM2_12 "电压稳定时间_IMM2";
CM_ SG_ 2332107421 CRC_M2I_Byrack_IMM2_13 "CRC校验_IMM2";
CM_ SG_ 2332107421 M2I_Byrack_HVS_IMM2_13 "绝缘测量电压_IMM2";
CM_ SG_ 2332107421 M2I_Byrack_Enable_IMM2_13 "绝缘采样使能位_IMM2";
CM_ SG_ 2332107421 M2I_Byrack_ReVeEnable_IMM2_13 "读取软件版本使能位_IMM2";
CM_ SG_ 2332107421 Reserved_13 "预留预留";
CM_ SG_ 2332107421 M2I_Byrack_IsPostTm_IMM2_13 "绝缘采样时间_IMM2";
CM_ SG_ 2332107421 M2I_Byrack_SysABStTm_IMM2_13 "电压稳定时间_IMM2";
CM_ SG_ 2332107422 CRC_M2I_Byrack_IMM2_14 "CRC校验_IMM2";
CM_ SG_ 2332107422 M2I_Byrack_HVS_IMM2_14 "绝缘测量电压_IMM2";
CM_ SG_ 2332107422 M2I_Byrack_Enable_IMM2_14 "绝缘采样使能位_IMM2";
CM_ SG_ 2332107422 M2I_Byrack_ReVeEnable_IMM2_14 "读取软件版本使能位_IMM2";
CM_ SG_ 2332107422 Reserved_14 "预留预留";
CM_ SG_ 2332107422 M2I_Byrack_IsPostTm_IMM2_14 "绝缘采样时间_IMM2";
CM_ SG_ 2332107422 M2I_Byrack_SysABStTm_IMM2_14 "电压稳定时间_IMM2";
CM_ SG_ 2332107423 CRC_M2I_Byrack_IMM2_15 "CRC校验_IMM2";
CM_ SG_ 2332107423 M2I_Byrack_HVS_IMM2_15 "绝缘测量电压_IMM2";
CM_ SG_ 2332107423 M2I_Byrack_Enable_IMM2_15 "绝缘采样使能位_IMM2";
CM_ SG_ 2332107423 M2I_Byrack_ReVeEnable_IMM2_15 "读取软件版本使能位_IMM2";
CM_ SG_ 2332107423 Reserved_15 "预留预留";
CM_ SG_ 2332107423 M2I_Byrack_IsPostTm_IMM2_15 "绝缘采样时间_IMM2";
CM_ SG_ 2332107423 M2I_Byrack_SysABStTm_IMM2_15 "电压稳定时间_IMM2";
CM_ SG_ 2332107424 CRC_M2I_Byrack_IMM2_16 "CRC校验_IMM2";
CM_ SG_ 2332107424 M2I_Byrack_HVS_IMM2_16 "绝缘测量电压_IMM2";
CM_ SG_ 2332107424 M2I_Byrack_Enable_IMM2_16 "绝缘采样使能位_IMM2";
CM_ SG_ 2332107424 M2I_Byrack_ReVeEnable_IMM2_16 "读取软件版本使能位_IMM2";
CM_ SG_ 2332107424 Reserved_16 "预留预留";
CM_ SG_ 2332107424 M2I_Byrack_IsPostTm_IMM2_16 "绝缘采样时间_IMM2";
CM_ SG_ 2332107424 M2I_Byrack_SysABStTm_IMM2_16 "电压稳定时间_IMM2";
CM_ SG_ 2332107425 CRC_M2I_Byrack_IMM2_17 "CRC校验_IMM2";
CM_ SG_ 2332107425 M2I_Byrack_HVS_IMM2_17 "绝缘测量电压_IMM2";
CM_ SG_ 2332107425 M2I_Byrack_Enable_IMM2_17 "绝缘采样使能位_IMM2";
CM_ SG_ 2332107425 M2I_Byrack_ReVeEnable_IMM2_17 "读取软件版本使能位_IMM2";
CM_ SG_ 2332107425 Reserved_17 "预留预留";
CM_ SG_ 2332107425 M2I_Byrack_IsPostTm_IMM2_17 "绝缘采样时间_IMM2";
CM_ SG_ 2332107425 M2I_Byrack_SysABStTm_IMM2_17 "电压稳定时间_IMM2";
CM_ SG_ 2332107426 CRC_M2I_Byrack_IMM2_18 "CRC校验_IMM2";
CM_ SG_ 2332107426 M2I_Byrack_HVS_IMM2_18 "绝缘测量电压_IMM2";
CM_ SG_ 2332107426 M2I_Byrack_Enable_IMM2_18 "绝缘采样使能位_IMM2";
CM_ SG_ 2332107426 M2I_Byrack_ReVeEnable_IMM2_18 "读取软件版本使能位_IMM2";
CM_ SG_ 2332107426 Reserved_18 "预留预留";
CM_ SG_ 2332107426 M2I_Byrack_IsPostTm_IMM2_18 "绝缘采样时间_IMM2";
CM_ SG_ 2332107426 M2I_Byrack_SysABStTm_IMM2_18 "电压稳定时间_IMM2";
CM_ SG_ 2332107427 CRC_M2I_Byrack_IMM2_19 "CRC校验_IMM2";
CM_ SG_ 2332107427 M2I_Byrack_HVS_IMM2_19 "绝缘测量电压_IMM2";
CM_ SG_ 2332107427 M2I_Byrack_Enable_IMM2_19 "绝缘采样使能位_IMM2";
CM_ SG_ 2332107427 M2I_Byrack_ReVeEnable_IMM2_19 "读取软件版本使能位_IMM2";
CM_ SG_ 2332107427 Reserved_19 "预留预留";
CM_ SG_ 2332107427 M2I_Byrack_IsPostTm_IMM2_19 "绝缘采样时间_IMM2";
CM_ SG_ 2332107427 M2I_Byrack_SysABStTm_IMM2_19 "电压稳定时间_IMM2";
CM_ SG_ 2332107428 CRC_M2I_Byrack_IMM2_20 "CRC校验_IMM2";
CM_ SG_ 2332107428 M2I_Byrack_HVS_IMM2_20 "绝缘测量电压_IMM2";
CM_ SG_ 2332107428 M2I_Byrack_Enable_IMM2_20 "绝缘采样使能位_IMM2";
CM_ SG_ 2332107428 M2I_Byrack_ReVeEnable_IMM2_20 "读取软件版本使能位_IMM2";
CM_ SG_ 2332107428 Reserved_20 "预留预留";
CM_ SG_ 2332107428 M2I_Byrack_IsPostTm_IMM2_20 "绝缘采样时间_IMM2";
CM_ SG_ 2332107428 M2I_Byrack_SysABStTm_IMM2_20 "电压稳定时间_IMM2";
CM_ SG_ 2332107429 CRC_M2I_Byrack_IMM2_21 "CRC校验_IMM2";
CM_ SG_ 2332107429 M2I_Byrack_HVS_IMM2_21 "绝缘测量电压_IMM2";
CM_ SG_ 2332107429 M2I_Byrack_Enable_IMM2_21 "绝缘采样使能位_IMM2";
CM_ SG_ 2332107429 M2I_Byrack_ReVeEnable_IMM2_21 "读取软件版本使能位_IMM2";
CM_ SG_ 2332107429 Reserved_21 "预留预留";
CM_ SG_ 2332107429 M2I_Byrack_IsPostTm_IMM2_21 "绝缘采样时间_IMM2";
CM_ SG_ 2332107429 M2I_Byrack_SysABStTm_IMM2_21 "电压稳定时间_IMM2";
CM_ SG_ 2332107430 CRC_M2I_Byrack_IMM2_22 "CRC校验_IMM2";
CM_ SG_ 2332107430 M2I_Byrack_HVS_IMM2_22 "绝缘测量电压_IMM2";
CM_ SG_ 2332107430 M2I_Byrack_Enable_IMM2_22 "绝缘采样使能位_IMM2";
CM_ SG_ 2332107430 M2I_Byrack_ReVeEnable_IMM2_22 "读取软件版本使能位_IMM2";
CM_ SG_ 2332107430 Reserved_22 "预留预留";
CM_ SG_ 2332107430 M2I_Byrack_IsPostTm_IMM2_22 "绝缘采样时间_IMM2";
CM_ SG_ 2332107430 M2I_Byrack_SysABStTm_IMM2_22 "电压稳定时间_IMM2";
CM_ SG_ 2332107431 CRC_M2I_Byrack_IMM2_23 "CRC校验_IMM2";
CM_ SG_ 2332107431 M2I_Byrack_HVS_IMM2_23 "绝缘测量电压_IMM2";
CM_ SG_ 2332107431 M2I_Byrack_Enable_IMM2_23 "绝缘采样使能位_IMM2";
CM_ SG_ 2332107431 M2I_Byrack_ReVeEnable_IMM2_23 "读取软件版本使能位_IMM2";
CM_ SG_ 2332107431 Reserved_23 "预留预留";
CM_ SG_ 2332107431 M2I_Byrack_IsPostTm_IMM2_23 "绝缘采样时间_IMM2";
CM_ SG_ 2332107431 M2I_Byrack_SysABStTm_IMM2_23 "电压稳定时间_IMM2";
CM_ SG_ 2332107432 CRC_M2I_Byrack_IMM2_24 "CRC校验_IMM2";
CM_ SG_ 2332107432 M2I_Byrack_HVS_IMM2_24 "绝缘测量电压_IMM2";
CM_ SG_ 2332107432 M2I_Byrack_Enable_IMM2_24 "绝缘采样使能位_IMM2";
CM_ SG_ 2332107432 M2I_Byrack_ReVeEnable_IMM2_24 "读取软件版本使能位_IMM2";
CM_ SG_ 2332107432 Reserved_24 "预留预留";
CM_ SG_ 2332107432 M2I_Byrack_IsPostTm_IMM2_24 "绝缘采样时间_IMM2";
CM_ SG_ 2332107432 M2I_Byrack_SysABStTm_IMM2_24 "电压稳定时间_IMM2";
CM_ SG_ 2332107433 CRC_M2I_Byrack_IMM2_25 "CRC校验_IMM2";
CM_ SG_ 2332107433 M2I_Byrack_HVS_IMM2_25 "绝缘测量电压_IMM2";
CM_ SG_ 2332107433 M2I_Byrack_Enable_IMM2_25 "绝缘采样使能位_IMM2";
CM_ SG_ 2332107433 M2I_Byrack_ReVeEnable_IMM2_25 "读取软件版本使能位_IMM2";
CM_ SG_ 2332107433 Reserved_25 "预留预留";
CM_ SG_ 2332107433 M2I_Byrack_IsPostTm_IMM2_25 "绝缘采样时间_IMM2";
CM_ SG_ 2332107433 M2I_Byrack_SysABStTm_IMM2_25 "电压稳定时间_IMM2";
CM_ SG_ 2332107434 CRC_M2I_Byrack_IMM2_26 "CRC校验_IMM2";
CM_ SG_ 2332107434 M2I_Byrack_HVS_IMM2_26 "绝缘测量电压_IMM2";
CM_ SG_ 2332107434 M2I_Byrack_Enable_IMM2_26 "绝缘采样使能位_IMM2";
CM_ SG_ 2332107434 M2I_Byrack_ReVeEnable_IMM2_26 "读取软件版本使能位_IMM2";
CM_ SG_ 2332107434 Reserved_26 "预留预留";
CM_ SG_ 2332107434 M2I_Byrack_IsPostTm_IMM2_26 "绝缘采样时间_IMM2";
CM_ SG_ 2332107434 M2I_Byrack_SysABStTm_IMM2_26 "电压稳定时间_IMM2";
CM_ SG_ 2332107435 CRC_M2I_Byrack_IMM2_27 "CRC校验_IMM2";
CM_ SG_ 2332107435 M2I_Byrack_HVS_IMM2_27 "绝缘测量电压_IMM2";
CM_ SG_ 2332107435 M2I_Byrack_Enable_IMM2_27 "绝缘采样使能位_IMM2";
CM_ SG_ 2332107435 M2I_Byrack_ReVeEnable_IMM2_27 "读取软件版本使能位_IMM2";
CM_ SG_ 2332107435 Reserved_27 "预留预留";
CM_ SG_ 2332107435 M2I_Byrack_IsPostTm_IMM2_27 "绝缘采样时间_IMM2";
CM_ SG_ 2332107435 M2I_Byrack_SysABStTm_IMM2_27 "电压稳定时间_IMM2";
CM_ SG_ 2332107436 CRC_M2I_Byrack_IMM2_28 "CRC校验_IMM2";
CM_ SG_ 2332107436 M2I_Byrack_HVS_IMM2_28 "绝缘测量电压_IMM2";
CM_ SG_ 2332107436 M2I_Byrack_Enable_IMM2_28 "绝缘采样使能位_IMM2";
CM_ SG_ 2332107436 M2I_Byrack_ReVeEnable_IMM2_28 "读取软件版本使能位_IMM2";
CM_ SG_ 2332107436 Reserved_28 "预留预留";
CM_ SG_ 2332107436 M2I_Byrack_IsPostTm_IMM2_28 "绝缘采样时间_IMM2";
CM_ SG_ 2332107436 M2I_Byrack_SysABStTm_IMM2_28 "电压稳定时间_IMM2";
CM_ SG_ 2332107437 CRC_M2I_Byrack_IMM2_29 "CRC校验_IMM2";
CM_ SG_ 2332107437 M2I_Byrack_HVS_IMM2_29 "绝缘测量电压_IMM2";
CM_ SG_ 2332107437 M2I_Byrack_Enable_IMM2_29 "绝缘采样使能位_IMM2";
CM_ SG_ 2332107437 M2I_Byrack_ReVeEnable_IMM2_29 "读取软件版本使能位_IMM2";
CM_ SG_ 2332107437 Reserved_29 "预留预留";
CM_ SG_ 2332107437 M2I_Byrack_IsPostTm_IMM2_29 "绝缘采样时间_IMM2";
CM_ SG_ 2332107437 M2I_Byrack_SysABStTm_IMM2_29 "电压稳定时间_IMM2";
CM_ SG_ 2332107438 CRC_M2I_Byrack_IMM2_30 "CRC校验_IMM2";
CM_ SG_ 2332107438 M2I_Byrack_HVS_IMM2_30 "绝缘测量电压_IMM2";
CM_ SG_ 2332107438 M2I_Byrack_Enable_IMM2_30 "绝缘采样使能位_IMM2";
CM_ SG_ 2332107438 M2I_Byrack_ReVeEnable_IMM2_30 "读取软件版本使能位_IMM2";
CM_ SG_ 2332107438 Reserved_30 "预留预留";
CM_ SG_ 2332107438 M2I_Byrack_IsPostTm_IMM2_30 "绝缘采样时间_IMM2";
CM_ SG_ 2332107438 M2I_Byrack_SysABStTm_IMM2_30 "电压稳定时间_IMM2";
CM_ SG_ 2332107439 CRC_M2I_Byrack_IMM2_31 "CRC校验_IMM2";
CM_ SG_ 2332107439 M2I_Byrack_HVS_IMM2_31 "绝缘测量电压_IMM2";
CM_ SG_ 2332107439 M2I_Byrack_Enable_IMM2_31 "绝缘采样使能位_IMM2";
CM_ SG_ 2332107439 M2I_Byrack_ReVeEnable_IMM2_31 "读取软件版本使能位_IMM2";
CM_ SG_ 2332107439 Reserved_31 "预留预留";
CM_ SG_ 2332107439 M2I_Byrack_IsPostTm_IMM2_31 "绝缘采样时间_IMM2";
CM_ SG_ 2332107439 M2I_Byrack_SysABStTm_IMM2_31 "电压稳定时间_IMM2";
CM_ SG_ 2332107665 CRC_M2I_Byrack_IMM3_01 "CRC校验_IMM3";
CM_ SG_ 2332107665 M2I_Byrack_HVS_IMM3_01 "绝缘测量电压_IMM3";
CM_ SG_ 2332107665 M2I_Byrack_Enable_IMM3_01 "绝缘采样使能位_IMM3";
CM_ SG_ 2332107665 M2I_Byrack_ReVeEnable_IMM3_01 "读取软件版本使能位_IMM3";
CM_ SG_ 2332107665 Reserved_01 "预留预留";
CM_ SG_ 2332107665 M2I_Byrack_IsPostTm_IMM3_01 "绝缘采样时间_IMM3";
CM_ SG_ 2332107665 M2I_Byrack_SysABStTm_IMM3_01 "电压稳定时间_IMM3";
CM_ SG_ 2332107666 CRC_M2I_Byrack_IMM3_02 "CRC校验_IMM3";
CM_ SG_ 2332107666 M2I_Byrack_HVS_IMM3_02 "绝缘测量电压_IMM3";
CM_ SG_ 2332107666 M2I_Byrack_Enable_IMM3_02 "绝缘采样使能位_IMM3";
CM_ SG_ 2332107666 M2I_Byrack_ReVeEnable_IMM3_02 "读取软件版本使能位_IMM3";
CM_ SG_ 2332107666 Reserved_02 "预留预留";
CM_ SG_ 2332107666 M2I_Byrack_IsPostTm_IMM3_02 "绝缘采样时间_IMM3";
CM_ SG_ 2332107666 M2I_Byrack_SysABStTm_IMM3_02 "电压稳定时间_IMM3";
CM_ SG_ 2332107667 CRC_M2I_Byrack_IMM3_03 "CRC校验_IMM3";
CM_ SG_ 2332107667 M2I_Byrack_HVS_IMM3_03 "绝缘测量电压_IMM3";
CM_ SG_ 2332107667 M2I_Byrack_Enable_IMM3_03 "绝缘采样使能位_IMM3";
CM_ SG_ 2332107667 M2I_Byrack_ReVeEnable_IMM3_03 "读取软件版本使能位_IMM3";
CM_ SG_ 2332107667 Reserved_03 "预留预留";
CM_ SG_ 2332107667 M2I_Byrack_IsPostTm_IMM3_03 "绝缘采样时间_IMM3";
CM_ SG_ 2332107667 M2I_Byrack_SysABStTm_IMM3_03 "电压稳定时间_IMM3";
CM_ SG_ 2332107668 CRC_M2I_Byrack_IMM3_04 "CRC校验_IMM3";
CM_ SG_ 2332107668 M2I_Byrack_HVS_IMM3_04 "绝缘测量电压_IMM3";
CM_ SG_ 2332107668 M2I_Byrack_Enable_IMM3_04 "绝缘采样使能位_IMM3";
CM_ SG_ 2332107668 M2I_Byrack_ReVeEnable_IMM3_04 "读取软件版本使能位_IMM3";
CM_ SG_ 2332107668 Reserved_04 "预留预留";
CM_ SG_ 2332107668 M2I_Byrack_IsPostTm_IMM3_04 "绝缘采样时间_IMM3";
CM_ SG_ 2332107668 M2I_Byrack_SysABStTm_IMM3_04 "电压稳定时间_IMM3";
CM_ SG_ 2332107669 CRC_M2I_Byrack_IMM3_05 "CRC校验_IMM3";
CM_ SG_ 2332107669 M2I_Byrack_HVS_IMM3_05 "绝缘测量电压_IMM3";
CM_ SG_ 2332107669 M2I_Byrack_Enable_IMM3_05 "绝缘采样使能位_IMM3";
CM_ SG_ 2332107669 M2I_Byrack_ReVeEnable_IMM3_05 "读取软件版本使能位_IMM3";
CM_ SG_ 2332107669 Reserved_05 "预留预留";
CM_ SG_ 2332107669 M2I_Byrack_IsPostTm_IMM3_05 "绝缘采样时间_IMM3";
CM_ SG_ 2332107669 M2I_Byrack_SysABStTm_IMM3_05 "电压稳定时间_IMM3";
CM_ SG_ 2332107670 CRC_M2I_Byrack_IMM3_06 "CRC校验_IMM3";
CM_ SG_ 2332107670 M2I_Byrack_HVS_IMM3_06 "绝缘测量电压_IMM3";
CM_ SG_ 2332107670 M2I_Byrack_Enable_IMM3_06 "绝缘采样使能位_IMM3";
CM_ SG_ 2332107670 M2I_Byrack_ReVeEnable_IMM3_06 "读取软件版本使能位_IMM3";
CM_ SG_ 2332107670 Reserved_06 "预留预留";
CM_ SG_ 2332107670 M2I_Byrack_IsPostTm_IMM3_06 "绝缘采样时间_IMM3";
CM_ SG_ 2332107670 M2I_Byrack_SysABStTm_IMM3_06 "电压稳定时间_IMM3";
CM_ SG_ 2332107671 CRC_M2I_Byrack_IMM3_07 "CRC校验_IMM3";
CM_ SG_ 2332107671 M2I_Byrack_HVS_IMM3_07 "绝缘测量电压_IMM3";
CM_ SG_ 2332107671 M2I_Byrack_Enable_IMM3_07 "绝缘采样使能位_IMM3";
CM_ SG_ 2332107671 M2I_Byrack_ReVeEnable_IMM3_07 "读取软件版本使能位_IMM3";
CM_ SG_ 2332107671 Reserved_07 "预留预留";
CM_ SG_ 2332107671 M2I_Byrack_IsPostTm_IMM3_07 "绝缘采样时间_IMM3";
CM_ SG_ 2332107671 M2I_Byrack_SysABStTm_IMM3_07 "电压稳定时间_IMM3";
CM_ SG_ 2332107672 CRC_M2I_Byrack_IMM3_08 "CRC校验_IMM3";
CM_ SG_ 2332107672 M2I_Byrack_HVS_IMM3_08 "绝缘测量电压_IMM3";
CM_ SG_ 2332107672 M2I_Byrack_Enable_IMM3_08 "绝缘采样使能位_IMM3";
CM_ SG_ 2332107672 M2I_Byrack_ReVeEnable_IMM3_08 "读取软件版本使能位_IMM3";
CM_ SG_ 2332107672 Reserved_08 "预留预留";
CM_ SG_ 2332107672 M2I_Byrack_IsPostTm_IMM3_08 "绝缘采样时间_IMM3";
CM_ SG_ 2332107672 M2I_Byrack_SysABStTm_IMM3_08 "电压稳定时间_IMM3";
CM_ SG_ 2332107673 CRC_M2I_Byrack_IMM3_09 "CRC校验_IMM3";
CM_ SG_ 2332107673 M2I_Byrack_HVS_IMM3_09 "绝缘测量电压_IMM3";
CM_ SG_ 2332107673 M2I_Byrack_Enable_IMM3_09 "绝缘采样使能位_IMM3";
CM_ SG_ 2332107673 M2I_Byrack_ReVeEnable_IMM3_09 "读取软件版本使能位_IMM3";
CM_ SG_ 2332107673 Reserved_09 "预留预留";
CM_ SG_ 2332107673 M2I_Byrack_IsPostTm_IMM3_09 "绝缘采样时间_IMM3";
CM_ SG_ 2332107673 M2I_Byrack_SysABStTm_IMM3_09 "电压稳定时间_IMM3";
CM_ SG_ 2332107674 CRC_M2I_Byrack_IMM3_10 "CRC校验_IMM3";
CM_ SG_ 2332107674 M2I_Byrack_HVS_IMM3_10 "绝缘测量电压_IMM3";
CM_ SG_ 2332107674 M2I_Byrack_Enable_IMM3_10 "绝缘采样使能位_IMM3";
CM_ SG_ 2332107674 M2I_Byrack_ReVeEnable_IMM3_10 "读取软件版本使能位_IMM3";
CM_ SG_ 2332107674 Reserved_10 "预留预留";
CM_ SG_ 2332107674 M2I_Byrack_IsPostTm_IMM3_10 "绝缘采样时间_IMM3";
CM_ SG_ 2332107674 M2I_Byrack_SysABStTm_IMM3_10 "电压稳定时间_IMM3";
CM_ SG_ 2332107675 CRC_M2I_Byrack_IMM3_11 "CRC校验_IMM3";
CM_ SG_ 2332107675 M2I_Byrack_HVS_IMM3_11 "绝缘测量电压_IMM3";
CM_ SG_ 2332107675 M2I_Byrack_Enable_IMM3_11 "绝缘采样使能位_IMM3";
CM_ SG_ 2332107675 M2I_Byrack_ReVeEnable_IMM3_11 "读取软件版本使能位_IMM3";
CM_ SG_ 2332107675 Reserved_11 "预留预留";
CM_ SG_ 2332107675 M2I_Byrack_IsPostTm_IMM3_11 "绝缘采样时间_IMM3";
CM_ SG_ 2332107675 M2I_Byrack_SysABStTm_IMM3_11 "电压稳定时间_IMM3";
CM_ SG_ 2332107676 CRC_M2I_Byrack_IMM3_12 "CRC校验_IMM3";
CM_ SG_ 2332107676 M2I_Byrack_HVS_IMM3_12 "绝缘测量电压_IMM3";
CM_ SG_ 2332107676 M2I_Byrack_Enable_IMM3_12 "绝缘采样使能位_IMM3";
CM_ SG_ 2332107676 M2I_Byrack_ReVeEnable_IMM3_12 "读取软件版本使能位_IMM3";
CM_ SG_ 2332107676 Reserved_12 "预留预留";
CM_ SG_ 2332107676 M2I_Byrack_IsPostTm_IMM3_12 "绝缘采样时间_IMM3";
CM_ SG_ 2332107676 M2I_Byrack_SysABStTm_IMM3_12 "电压稳定时间_IMM3";
CM_ SG_ 2332107677 CRC_M2I_Byrack_IMM3_13 "CRC校验_IMM3";
CM_ SG_ 2332107677 M2I_Byrack_HVS_IMM3_13 "绝缘测量电压_IMM3";
CM_ SG_ 2332107677 M2I_Byrack_Enable_IMM3_13 "绝缘采样使能位_IMM3";
CM_ SG_ 2332107677 M2I_Byrack_ReVeEnable_IMM3_13 "读取软件版本使能位_IMM3";
CM_ SG_ 2332107677 Reserved_13 "预留预留";
CM_ SG_ 2332107677 M2I_Byrack_IsPostTm_IMM3_13 "绝缘采样时间_IMM3";
CM_ SG_ 2332107677 M2I_Byrack_SysABStTm_IMM3_13 "电压稳定时间_IMM3";
CM_ SG_ 2332107678 CRC_M2I_Byrack_IMM3_14 "CRC校验_IMM3";
CM_ SG_ 2332107678 M2I_Byrack_HVS_IMM3_14 "绝缘测量电压_IMM3";
CM_ SG_ 2332107678 M2I_Byrack_Enable_IMM3_14 "绝缘采样使能位_IMM3";
CM_ SG_ 2332107678 M2I_Byrack_ReVeEnable_IMM3_14 "读取软件版本使能位_IMM3";
CM_ SG_ 2332107678 Reserved_14 "预留预留";
CM_ SG_ 2332107678 M2I_Byrack_IsPostTm_IMM3_14 "绝缘采样时间_IMM3";
CM_ SG_ 2332107678 M2I_Byrack_SysABStTm_IMM3_14 "电压稳定时间_IMM3";
CM_ SG_ 2332107679 CRC_M2I_Byrack_IMM3_15 "CRC校验_IMM3";
CM_ SG_ 2332107679 M2I_Byrack_HVS_IMM3_15 "绝缘测量电压_IMM3";
CM_ SG_ 2332107679 M2I_Byrack_Enable_IMM3_15 "绝缘采样使能位_IMM3";
CM_ SG_ 2332107679 M2I_Byrack_ReVeEnable_IMM3_15 "读取软件版本使能位_IMM3";
CM_ SG_ 2332107679 Reserved_15 "预留预留";
CM_ SG_ 2332107679 M2I_Byrack_IsPostTm_IMM3_15 "绝缘采样时间_IMM3";
CM_ SG_ 2332107679 M2I_Byrack_SysABStTm_IMM3_15 "电压稳定时间_IMM3";
CM_ SG_ 2332107680 CRC_M2I_Byrack_IMM3_16 "CRC校验_IMM3";
CM_ SG_ 2332107680 M2I_Byrack_HVS_IMM3_16 "绝缘测量电压_IMM3";
CM_ SG_ 2332107680 M2I_Byrack_Enable_IMM3_16 "绝缘采样使能位_IMM3";
CM_ SG_ 2332107680 M2I_Byrack_ReVeEnable_IMM3_16 "读取软件版本使能位_IMM3";
CM_ SG_ 2332107680 Reserved_16 "预留预留";
CM_ SG_ 2332107680 M2I_Byrack_IsPostTm_IMM3_16 "绝缘采样时间_IMM3";
CM_ SG_ 2332107680 M2I_Byrack_SysABStTm_IMM3_16 "电压稳定时间_IMM3";
CM_ SG_ 2332107681 CRC_M2I_Byrack_IMM3_17 "CRC校验_IMM3";
CM_ SG_ 2332107681 M2I_Byrack_HVS_IMM3_17 "绝缘测量电压_IMM3";
CM_ SG_ 2332107681 M2I_Byrack_Enable_IMM3_17 "绝缘采样使能位_IMM3";
CM_ SG_ 2332107681 M2I_Byrack_ReVeEnable_IMM3_17 "读取软件版本使能位_IMM3";
CM_ SG_ 2332107681 Reserved_17 "预留预留";
CM_ SG_ 2332107681 M2I_Byrack_IsPostTm_IMM3_17 "绝缘采样时间_IMM3";
CM_ SG_ 2332107681 M2I_Byrack_SysABStTm_IMM3_17 "电压稳定时间_IMM3";
CM_ SG_ 2332107682 CRC_M2I_Byrack_IMM3_18 "CRC校验_IMM3";
CM_ SG_ 2332107682 M2I_Byrack_HVS_IMM3_18 "绝缘测量电压_IMM3";
CM_ SG_ 2332107682 M2I_Byrack_Enable_IMM3_18 "绝缘采样使能位_IMM3";
CM_ SG_ 2332107682 M2I_Byrack_ReVeEnable_IMM3_18 "读取软件版本使能位_IMM3";
CM_ SG_ 2332107682 Reserved_18 "预留预留";
CM_ SG_ 2332107682 M2I_Byrack_IsPostTm_IMM3_18 "绝缘采样时间_IMM3";
CM_ SG_ 2332107682 M2I_Byrack_SysABStTm_IMM3_18 "电压稳定时间_IMM3";
CM_ SG_ 2332107683 CRC_M2I_Byrack_IMM3_19 "CRC校验_IMM3";
CM_ SG_ 2332107683 M2I_Byrack_HVS_IMM3_19 "绝缘测量电压_IMM3";
CM_ SG_ 2332107683 M2I_Byrack_Enable_IMM3_19 "绝缘采样使能位_IMM3";
CM_ SG_ 2332107683 M2I_Byrack_ReVeEnable_IMM3_19 "读取软件版本使能位_IMM3";
CM_ SG_ 2332107683 Reserved_19 "预留预留";
CM_ SG_ 2332107683 M2I_Byrack_IsPostTm_IMM3_19 "绝缘采样时间_IMM3";
CM_ SG_ 2332107683 M2I_Byrack_SysABStTm_IMM3_19 "电压稳定时间_IMM3";
CM_ SG_ 2332107684 CRC_M2I_Byrack_IMM3_20 "CRC校验_IMM3";
CM_ SG_ 2332107684 M2I_Byrack_HVS_IMM3_20 "绝缘测量电压_IMM3";
CM_ SG_ 2332107684 M2I_Byrack_Enable_IMM3_20 "绝缘采样使能位_IMM3";
CM_ SG_ 2332107684 M2I_Byrack_ReVeEnable_IMM3_20 "读取软件版本使能位_IMM3";
CM_ SG_ 2332107684 Reserved_20 "预留预留";
CM_ SG_ 2332107684 M2I_Byrack_IsPostTm_IMM3_20 "绝缘采样时间_IMM3";
CM_ SG_ 2332107684 M2I_Byrack_SysABStTm_IMM3_20 "电压稳定时间_IMM3";
CM_ SG_ 2332107685 CRC_M2I_Byrack_IMM3_21 "CRC校验_IMM3";
CM_ SG_ 2332107685 M2I_Byrack_HVS_IMM3_21 "绝缘测量电压_IMM3";
CM_ SG_ 2332107685 M2I_Byrack_Enable_IMM3_21 "绝缘采样使能位_IMM3";
CM_ SG_ 2332107685 M2I_Byrack_ReVeEnable_IMM3_21 "读取软件版本使能位_IMM3";
CM_ SG_ 2332107685 Reserved_21 "预留预留";
CM_ SG_ 2332107685 M2I_Byrack_IsPostTm_IMM3_21 "绝缘采样时间_IMM3";
CM_ SG_ 2332107685 M2I_Byrack_SysABStTm_IMM3_21 "电压稳定时间_IMM3";
CM_ SG_ 2332107686 CRC_M2I_Byrack_IMM3_22 "CRC校验_IMM3";
CM_ SG_ 2332107686 M2I_Byrack_HVS_IMM3_22 "绝缘测量电压_IMM3";
CM_ SG_ 2332107686 M2I_Byrack_Enable_IMM3_22 "绝缘采样使能位_IMM3";
CM_ SG_ 2332107686 M2I_Byrack_ReVeEnable_IMM3_22 "读取软件版本使能位_IMM3";
CM_ SG_ 2332107686 Reserved_22 "预留预留";
CM_ SG_ 2332107686 M2I_Byrack_IsPostTm_IMM3_22 "绝缘采样时间_IMM3";
CM_ SG_ 2332107686 M2I_Byrack_SysABStTm_IMM3_22 "电压稳定时间_IMM3";
CM_ SG_ 2332107687 CRC_M2I_Byrack_IMM3_23 "CRC校验_IMM3";
CM_ SG_ 2332107687 M2I_Byrack_HVS_IMM3_23 "绝缘测量电压_IMM3";
CM_ SG_ 2332107687 M2I_Byrack_Enable_IMM3_23 "绝缘采样使能位_IMM3";
CM_ SG_ 2332107687 M2I_Byrack_ReVeEnable_IMM3_23 "读取软件版本使能位_IMM3";
CM_ SG_ 2332107687 Reserved_23 "预留预留";
CM_ SG_ 2332107687 M2I_Byrack_IsPostTm_IMM3_23 "绝缘采样时间_IMM3";
CM_ SG_ 2332107687 M2I_Byrack_SysABStTm_IMM3_23 "电压稳定时间_IMM3";
CM_ SG_ 2332107688 CRC_M2I_Byrack_IMM3_24 "CRC校验_IMM3";
CM_ SG_ 2332107688 M2I_Byrack_HVS_IMM3_24 "绝缘测量电压_IMM3";
CM_ SG_ 2332107688 M2I_Byrack_Enable_IMM3_24 "绝缘采样使能位_IMM3";
CM_ SG_ 2332107688 M2I_Byrack_ReVeEnable_IMM3_24 "读取软件版本使能位_IMM3";
CM_ SG_ 2332107688 Reserved_24 "预留预留";
CM_ SG_ 2332107688 M2I_Byrack_IsPostTm_IMM3_24 "绝缘采样时间_IMM3";
CM_ SG_ 2332107688 M2I_Byrack_SysABStTm_IMM3_24 "电压稳定时间_IMM3";
CM_ SG_ 2332107689 CRC_M2I_Byrack_IMM3_25 "CRC校验_IMM3";
CM_ SG_ 2332107689 M2I_Byrack_HVS_IMM3_25 "绝缘测量电压_IMM3";
CM_ SG_ 2332107689 M2I_Byrack_Enable_IMM3_25 "绝缘采样使能位_IMM3";
CM_ SG_ 2332107689 M2I_Byrack_ReVeEnable_IMM3_25 "读取软件版本使能位_IMM3";
CM_ SG_ 2332107689 Reserved_25 "预留预留";
CM_ SG_ 2332107689 M2I_Byrack_IsPostTm_IMM3_25 "绝缘采样时间_IMM3";
CM_ SG_ 2332107689 M2I_Byrack_SysABStTm_IMM3_25 "电压稳定时间_IMM3";
CM_ SG_ 2332107690 CRC_M2I_Byrack_IMM3_26 "CRC校验_IMM3";
CM_ SG_ 2332107690 M2I_Byrack_HVS_IMM3_26 "绝缘测量电压_IMM3";
CM_ SG_ 2332107690 M2I_Byrack_Enable_IMM3_26 "绝缘采样使能位_IMM3";
CM_ SG_ 2332107690 M2I_Byrack_ReVeEnable_IMM3_26 "读取软件版本使能位_IMM3";
CM_ SG_ 2332107690 Reserved_26 "预留预留";
CM_ SG_ 2332107690 M2I_Byrack_IsPostTm_IMM3_26 "绝缘采样时间_IMM3";
CM_ SG_ 2332107690 M2I_Byrack_SysABStTm_IMM3_26 "电压稳定时间_IMM3";
CM_ SG_ 2332107691 CRC_M2I_Byrack_IMM3_27 "CRC校验_IMM3";
CM_ SG_ 2332107691 M2I_Byrack_HVS_IMM3_27 "绝缘测量电压_IMM3";
CM_ SG_ 2332107691 M2I_Byrack_Enable_IMM3_27 "绝缘采样使能位_IMM3";
CM_ SG_ 2332107691 M2I_Byrack_ReVeEnable_IMM3_27 "读取软件版本使能位_IMM3";
CM_ SG_ 2332107691 Reserved_27 "预留预留";
CM_ SG_ 2332107691 M2I_Byrack_IsPostTm_IMM3_27 "绝缘采样时间_IMM3";
CM_ SG_ 2332107691 M2I_Byrack_SysABStTm_IMM3_27 "电压稳定时间_IMM3";
CM_ SG_ 2332107692 CRC_M2I_Byrack_IMM3_28 "CRC校验_IMM3";
CM_ SG_ 2332107692 M2I_Byrack_HVS_IMM3_28 "绝缘测量电压_IMM3";
CM_ SG_ 2332107692 M2I_Byrack_Enable_IMM3_28 "绝缘采样使能位_IMM3";
CM_ SG_ 2332107692 M2I_Byrack_ReVeEnable_IMM3_28 "读取软件版本使能位_IMM3";
CM_ SG_ 2332107692 Reserved_28 "预留预留";
CM_ SG_ 2332107692 M2I_Byrack_IsPostTm_IMM3_28 "绝缘采样时间_IMM3";
CM_ SG_ 2332107692 M2I_Byrack_SysABStTm_IMM3_28 "电压稳定时间_IMM3";
CM_ SG_ 2332107693 CRC_M2I_Byrack_IMM3_29 "CRC校验_IMM3";
CM_ SG_ 2332107693 M2I_Byrack_HVS_IMM3_29 "绝缘测量电压_IMM3";
CM_ SG_ 2332107693 M2I_Byrack_Enable_IMM3_29 "绝缘采样使能位_IMM3";
CM_ SG_ 2332107693 M2I_Byrack_ReVeEnable_IMM3_29 "读取软件版本使能位_IMM3";
CM_ SG_ 2332107693 Reserved_29 "预留预留";
CM_ SG_ 2332107693 M2I_Byrack_IsPostTm_IMM3_29 "绝缘采样时间_IMM3";
CM_ SG_ 2332107693 M2I_Byrack_SysABStTm_IMM3_29 "电压稳定时间_IMM3";
CM_ SG_ 2332107694 CRC_M2I_Byrack_IMM3_30 "CRC校验_IMM3";
CM_ SG_ 2332107694 M2I_Byrack_HVS_IMM3_30 "绝缘测量电压_IMM3";
CM_ SG_ 2332107694 M2I_Byrack_Enable_IMM3_30 "绝缘采样使能位_IMM3";
CM_ SG_ 2332107694 M2I_Byrack_ReVeEnable_IMM3_30 "读取软件版本使能位_IMM3";
CM_ SG_ 2332107694 Reserved_30 "预留预留";
CM_ SG_ 2332107694 M2I_Byrack_IsPostTm_IMM3_30 "绝缘采样时间_IMM3";
CM_ SG_ 2332107694 M2I_Byrack_SysABStTm_IMM3_30 "电压稳定时间_IMM3";
CM_ SG_ 2332107695 CRC_M2I_Byrack_IMM3_31 "CRC校验_IMM3";
CM_ SG_ 2332107695 M2I_Byrack_HVS_IMM3_31 "绝缘测量电压_IMM3";
CM_ SG_ 2332107695 M2I_Byrack_Enable_IMM3_31 "绝缘采样使能位_IMM3";
CM_ SG_ 2332107695 M2I_Byrack_ReVeEnable_IMM3_31 "读取软件版本使能位_IMM3";
CM_ SG_ 2332107695 Reserved_31 "预留预留";
CM_ SG_ 2332107695 M2I_Byrack_IsPostTm_IMM3_31 "绝缘采样时间_IMM3";
CM_ SG_ 2332107695 M2I_Byrack_SysABStTm_IMM3_31 "电压稳定时间_IMM3";
CM_ SG_ 2332107921 CRC_M2I_Byrack_IMM4_01 "CRC校验_IMM4";
CM_ SG_ 2332107921 M2I_Byrack_HVS_IMM4_01 "绝缘测量电压_IMM4";
CM_ SG_ 2332107921 M2I_Byrack_Enable_IMM4_01 "绝缘采样使能位_IMM4";
CM_ SG_ 2332107921 M2I_Byrack_ReVeEnable_IMM4_01 "读取软件版本使能位_IMM4";
CM_ SG_ 2332107921 Reserved_01 "预留预留";
CM_ SG_ 2332107921 M2I_Byrack_IsPostTm_IMM4_01 "绝缘采样时间_IMM4";
CM_ SG_ 2332107921 M2I_Byrack_SysABStTm_IMM4_01 "电压稳定时间_IMM4";
CM_ SG_ 2332107922 CRC_M2I_Byrack_IMM4_02 "CRC校验_IMM4";
CM_ SG_ 2332107922 M2I_Byrack_HVS_IMM4_02 "绝缘测量电压_IMM4";
CM_ SG_ 2332107922 M2I_Byrack_Enable_IMM4_02 "绝缘采样使能位_IMM4";
CM_ SG_ 2332107922 M2I_Byrack_ReVeEnable_IMM4_02 "读取软件版本使能位_IMM4";
CM_ SG_ 2332107922 Reserved_02 "预留预留";
CM_ SG_ 2332107922 M2I_Byrack_IsPostTm_IMM4_02 "绝缘采样时间_IMM4";
CM_ SG_ 2332107922 M2I_Byrack_SysABStTm_IMM4_02 "电压稳定时间_IMM4";
CM_ SG_ 2332107923 CRC_M2I_Byrack_IMM4_03 "CRC校验_IMM4";
CM_ SG_ 2332107923 M2I_Byrack_HVS_IMM4_03 "绝缘测量电压_IMM4";
CM_ SG_ 2332107923 M2I_Byrack_Enable_IMM4_03 "绝缘采样使能位_IMM4";
CM_ SG_ 2332107923 M2I_Byrack_ReVeEnable_IMM4_03 "读取软件版本使能位_IMM4";
CM_ SG_ 2332107923 Reserved_03 "预留预留";
CM_ SG_ 2332107923 M2I_Byrack_IsPostTm_IMM4_03 "绝缘采样时间_IMM4";
CM_ SG_ 2332107923 M2I_Byrack_SysABStTm_IMM4_03 "电压稳定时间_IMM4";
CM_ SG_ 2332107924 CRC_M2I_Byrack_IMM4_04 "CRC校验_IMM4";
CM_ SG_ 2332107924 M2I_Byrack_HVS_IMM4_04 "绝缘测量电压_IMM4";
CM_ SG_ 2332107924 M2I_Byrack_Enable_IMM4_04 "绝缘采样使能位_IMM4";
CM_ SG_ 2332107924 M2I_Byrack_ReVeEnable_IMM4_04 "读取软件版本使能位_IMM4";
CM_ SG_ 2332107924 Reserved_04 "预留预留";
CM_ SG_ 2332107924 M2I_Byrack_IsPostTm_IMM4_04 "绝缘采样时间_IMM4";
CM_ SG_ 2332107924 M2I_Byrack_SysABStTm_IMM4_04 "电压稳定时间_IMM4";
CM_ SG_ 2332107925 CRC_M2I_Byrack_IMM4_05 "CRC校验_IMM4";
CM_ SG_ 2332107925 M2I_Byrack_HVS_IMM4_05 "绝缘测量电压_IMM4";
CM_ SG_ 2332107925 M2I_Byrack_Enable_IMM4_05 "绝缘采样使能位_IMM4";
CM_ SG_ 2332107925 M2I_Byrack_ReVeEnable_IMM4_05 "读取软件版本使能位_IMM4";
CM_ SG_ 2332107925 Reserved_05 "预留预留";
CM_ SG_ 2332107925 M2I_Byrack_IsPostTm_IMM4_05 "绝缘采样时间_IMM4";
CM_ SG_ 2332107925 M2I_Byrack_SysABStTm_IMM4_05 "电压稳定时间_IMM4";
CM_ SG_ 2332107926 CRC_M2I_Byrack_IMM4_06 "CRC校验_IMM4";
CM_ SG_ 2332107926 M2I_Byrack_HVS_IMM4_06 "绝缘测量电压_IMM4";
CM_ SG_ 2332107926 M2I_Byrack_Enable_IMM4_06 "绝缘采样使能位_IMM4";
CM_ SG_ 2332107926 M2I_Byrack_ReVeEnable_IMM4_06 "读取软件版本使能位_IMM4";
CM_ SG_ 2332107926 Reserved_06 "预留预留";
CM_ SG_ 2332107926 M2I_Byrack_IsPostTm_IMM4_06 "绝缘采样时间_IMM4";
CM_ SG_ 2332107926 M2I_Byrack_SysABStTm_IMM4_06 "电压稳定时间_IMM4";
CM_ SG_ 2332107927 CRC_M2I_Byrack_IMM4_07 "CRC校验_IMM4";
CM_ SG_ 2332107927 M2I_Byrack_HVS_IMM4_07 "绝缘测量电压_IMM4";
CM_ SG_ 2332107927 M2I_Byrack_Enable_IMM4_07 "绝缘采样使能位_IMM4";
CM_ SG_ 2332107927 M2I_Byrack_ReVeEnable_IMM4_07 "读取软件版本使能位_IMM4";
CM_ SG_ 2332107927 Reserved_07 "预留预留";
CM_ SG_ 2332107927 M2I_Byrack_IsPostTm_IMM4_07 "绝缘采样时间_IMM4";
CM_ SG_ 2332107927 M2I_Byrack_SysABStTm_IMM4_07 "电压稳定时间_IMM4";
CM_ SG_ 2332107928 CRC_M2I_Byrack_IMM4_08 "CRC校验_IMM4";
CM_ SG_ 2332107928 M2I_Byrack_HVS_IMM4_08 "绝缘测量电压_IMM4";
CM_ SG_ 2332107928 M2I_Byrack_Enable_IMM4_08 "绝缘采样使能位_IMM4";
CM_ SG_ 2332107928 M2I_Byrack_ReVeEnable_IMM4_08 "读取软件版本使能位_IMM4";
CM_ SG_ 2332107928 Reserved_08 "预留预留";
CM_ SG_ 2332107928 M2I_Byrack_IsPostTm_IMM4_08 "绝缘采样时间_IMM4";
CM_ SG_ 2332107928 M2I_Byrack_SysABStTm_IMM4_08 "电压稳定时间_IMM4";
CM_ SG_ 2332107929 CRC_M2I_Byrack_IMM4_09 "CRC校验_IMM4";
CM_ SG_ 2332107929 M2I_Byrack_HVS_IMM4_09 "绝缘测量电压_IMM4";
CM_ SG_ 2332107929 M2I_Byrack_Enable_IMM4_09 "绝缘采样使能位_IMM4";
CM_ SG_ 2332107929 M2I_Byrack_ReVeEnable_IMM4_09 "读取软件版本使能位_IMM4";
CM_ SG_ 2332107929 Reserved_09 "预留预留";
CM_ SG_ 2332107929 M2I_Byrack_IsPostTm_IMM4_09 "绝缘采样时间_IMM4";
CM_ SG_ 2332107929 M2I_Byrack_SysABStTm_IMM4_09 "电压稳定时间_IMM4";
CM_ SG_ 2332107930 CRC_M2I_Byrack_IMM4_10 "CRC校验_IMM4";
CM_ SG_ 2332107930 M2I_Byrack_HVS_IMM4_10 "绝缘测量电压_IMM4";
CM_ SG_ 2332107930 M2I_Byrack_Enable_IMM4_10 "绝缘采样使能位_IMM4";
CM_ SG_ 2332107930 M2I_Byrack_ReVeEnable_IMM4_10 "读取软件版本使能位_IMM4";
CM_ SG_ 2332107930 Reserved_10 "预留预留";
CM_ SG_ 2332107930 M2I_Byrack_IsPostTm_IMM4_10 "绝缘采样时间_IMM4";
CM_ SG_ 2332107930 M2I_Byrack_SysABStTm_IMM4_10 "电压稳定时间_IMM4";
CM_ SG_ 2332107931 CRC_M2I_Byrack_IMM4_11 "CRC校验_IMM4";
CM_ SG_ 2332107931 M2I_Byrack_HVS_IMM4_11 "绝缘测量电压_IMM4";
CM_ SG_ 2332107931 M2I_Byrack_Enable_IMM4_11 "绝缘采样使能位_IMM4";
CM_ SG_ 2332107931 M2I_Byrack_ReVeEnable_IMM4_11 "读取软件版本使能位_IMM4";
CM_ SG_ 2332107931 Reserved_11 "预留预留";
CM_ SG_ 2332107931 M2I_Byrack_IsPostTm_IMM4_11 "绝缘采样时间_IMM4";
CM_ SG_ 2332107931 M2I_Byrack_SysABStTm_IMM4_11 "电压稳定时间_IMM4";
CM_ SG_ 2332107932 CRC_M2I_Byrack_IMM4_12 "CRC校验_IMM4";
CM_ SG_ 2332107932 M2I_Byrack_HVS_IMM4_12 "绝缘测量电压_IMM4";
CM_ SG_ 2332107932 M2I_Byrack_Enable_IMM4_12 "绝缘采样使能位_IMM4";
CM_ SG_ 2332107932 M2I_Byrack_ReVeEnable_IMM4_12 "读取软件版本使能位_IMM4";
CM_ SG_ 2332107932 Reserved_12 "预留预留";
CM_ SG_ 2332107932 M2I_Byrack_IsPostTm_IMM4_12 "绝缘采样时间_IMM4";
CM_ SG_ 2332107932 M2I_Byrack_SysABStTm_IMM4_12 "电压稳定时间_IMM4";
CM_ SG_ 2332107933 CRC_M2I_Byrack_IMM4_13 "CRC校验_IMM4";
CM_ SG_ 2332107933 M2I_Byrack_HVS_IMM4_13 "绝缘测量电压_IMM4";
CM_ SG_ 2332107933 M2I_Byrack_Enable_IMM4_13 "绝缘采样使能位_IMM4";
CM_ SG_ 2332107933 M2I_Byrack_ReVeEnable_IMM4_13 "读取软件版本使能位_IMM4";
CM_ SG_ 2332107933 Reserved_13 "预留预留";
CM_ SG_ 2332107933 M2I_Byrack_IsPostTm_IMM4_13 "绝缘采样时间_IMM4";
CM_ SG_ 2332107933 M2I_Byrack_SysABStTm_IMM4_13 "电压稳定时间_IMM4";
CM_ SG_ 2332107934 CRC_M2I_Byrack_IMM4_14 "CRC校验_IMM4";
CM_ SG_ 2332107934 M2I_Byrack_HVS_IMM4_14 "绝缘测量电压_IMM4";
CM_ SG_ 2332107934 M2I_Byrack_Enable_IMM4_14 "绝缘采样使能位_IMM4";
CM_ SG_ 2332107934 M2I_Byrack_ReVeEnable_IMM4_14 "读取软件版本使能位_IMM4";
CM_ SG_ 2332107934 Reserved_14 "预留预留";
CM_ SG_ 2332107934 M2I_Byrack_IsPostTm_IMM4_14 "绝缘采样时间_IMM4";
CM_ SG_ 2332107934 M2I_Byrack_SysABStTm_IMM4_14 "电压稳定时间_IMM4";
CM_ SG_ 2332107935 CRC_M2I_Byrack_IMM4_15 "CRC校验_IMM4";
CM_ SG_ 2332107935 M2I_Byrack_HVS_IMM4_15 "绝缘测量电压_IMM4";
CM_ SG_ 2332107935 M2I_Byrack_Enable_IMM4_15 "绝缘采样使能位_IMM4";
CM_ SG_ 2332107935 M2I_Byrack_ReVeEnable_IMM4_15 "读取软件版本使能位_IMM4";
CM_ SG_ 2332107935 Reserved_15 "预留预留";
CM_ SG_ 2332107935 M2I_Byrack_IsPostTm_IMM4_15 "绝缘采样时间_IMM4";
CM_ SG_ 2332107935 M2I_Byrack_SysABStTm_IMM4_15 "电压稳定时间_IMM4";
CM_ SG_ 2332107936 CRC_M2I_Byrack_IMM4_16 "CRC校验_IMM4";
CM_ SG_ 2332107936 M2I_Byrack_HVS_IMM4_16 "绝缘测量电压_IMM4";
CM_ SG_ 2332107936 M2I_Byrack_Enable_IMM4_16 "绝缘采样使能位_IMM4";
CM_ SG_ 2332107936 M2I_Byrack_ReVeEnable_IMM4_16 "读取软件版本使能位_IMM4";
CM_ SG_ 2332107936 Reserved_16 "预留预留";
CM_ SG_ 2332107936 M2I_Byrack_IsPostTm_IMM4_16 "绝缘采样时间_IMM4";
CM_ SG_ 2332107936 M2I_Byrack_SysABStTm_IMM4_16 "电压稳定时间_IMM4";
CM_ SG_ 2332107937 CRC_M2I_Byrack_IMM4_17 "CRC校验_IMM4";
CM_ SG_ 2332107937 M2I_Byrack_HVS_IMM4_17 "绝缘测量电压_IMM4";
CM_ SG_ 2332107937 M2I_Byrack_Enable_IMM4_17 "绝缘采样使能位_IMM4";
CM_ SG_ 2332107937 M2I_Byrack_ReVeEnable_IMM4_17 "读取软件版本使能位_IMM4";
CM_ SG_ 2332107937 Reserved_17 "预留预留";
CM_ SG_ 2332107937 M2I_Byrack_IsPostTm_IMM4_17 "绝缘采样时间_IMM4";
CM_ SG_ 2332107937 M2I_Byrack_SysABStTm_IMM4_17 "电压稳定时间_IMM4";
CM_ SG_ 2332107938 CRC_M2I_Byrack_IMM4_18 "CRC校验_IMM4";
CM_ SG_ 2332107938 M2I_Byrack_HVS_IMM4_18 "绝缘测量电压_IMM4";
CM_ SG_ 2332107938 M2I_Byrack_Enable_IMM4_18 "绝缘采样使能位_IMM4";
CM_ SG_ 2332107938 M2I_Byrack_ReVeEnable_IMM4_18 "读取软件版本使能位_IMM4";
CM_ SG_ 2332107938 Reserved_18 "预留预留";
CM_ SG_ 2332107938 M2I_Byrack_IsPostTm_IMM4_18 "绝缘采样时间_IMM4";
CM_ SG_ 2332107938 M2I_Byrack_SysABStTm_IMM4_18 "电压稳定时间_IMM4";
CM_ SG_ 2332107939 CRC_M2I_Byrack_IMM4_19 "CRC校验_IMM4";
CM_ SG_ 2332107939 M2I_Byrack_HVS_IMM4_19 "绝缘测量电压_IMM4";
CM_ SG_ 2332107939 M2I_Byrack_Enable_IMM4_19 "绝缘采样使能位_IMM4";
CM_ SG_ 2332107939 M2I_Byrack_ReVeEnable_IMM4_19 "读取软件版本使能位_IMM4";
CM_ SG_ 2332107939 Reserved_19 "预留预留";
CM_ SG_ 2332107939 M2I_Byrack_IsPostTm_IMM4_19 "绝缘采样时间_IMM4";
CM_ SG_ 2332107939 M2I_Byrack_SysABStTm_IMM4_19 "电压稳定时间_IMM4";
CM_ SG_ 2332107940 CRC_M2I_Byrack_IMM4_20 "CRC校验_IMM4";
CM_ SG_ 2332107940 M2I_Byrack_HVS_IMM4_20 "绝缘测量电压_IMM4";
CM_ SG_ 2332107940 M2I_Byrack_Enable_IMM4_20 "绝缘采样使能位_IMM4";
CM_ SG_ 2332107940 M2I_Byrack_ReVeEnable_IMM4_20 "读取软件版本使能位_IMM4";
CM_ SG_ 2332107940 Reserved_20 "预留预留";
CM_ SG_ 2332107940 M2I_Byrack_IsPostTm_IMM4_20 "绝缘采样时间_IMM4";
CM_ SG_ 2332107940 M2I_Byrack_SysABStTm_IMM4_20 "电压稳定时间_IMM4";
CM_ SG_ 2332107941 CRC_M2I_Byrack_IMM4_21 "CRC校验_IMM4";
CM_ SG_ 2332107941 M2I_Byrack_HVS_IMM4_21 "绝缘测量电压_IMM4";
CM_ SG_ 2332107941 M2I_Byrack_Enable_IMM4_21 "绝缘采样使能位_IMM4";
CM_ SG_ 2332107941 M2I_Byrack_ReVeEnable_IMM4_21 "读取软件版本使能位_IMM4";
CM_ SG_ 2332107941 Reserved_21 "预留预留";
CM_ SG_ 2332107941 M2I_Byrack_IsPostTm_IMM4_21 "绝缘采样时间_IMM4";
CM_ SG_ 2332107941 M2I_Byrack_SysABStTm_IMM4_21 "电压稳定时间_IMM4";
CM_ SG_ 2332107942 CRC_M2I_Byrack_IMM4_22 "CRC校验_IMM4";
CM_ SG_ 2332107942 M2I_Byrack_HVS_IMM4_22 "绝缘测量电压_IMM4";
CM_ SG_ 2332107942 M2I_Byrack_Enable_IMM4_22 "绝缘采样使能位_IMM4";
CM_ SG_ 2332107942 M2I_Byrack_ReVeEnable_IMM4_22 "读取软件版本使能位_IMM4";
CM_ SG_ 2332107942 Reserved_22 "预留预留";
CM_ SG_ 2332107942 M2I_Byrack_IsPostTm_IMM4_22 "绝缘采样时间_IMM4";
CM_ SG_ 2332107942 M2I_Byrack_SysABStTm_IMM4_22 "电压稳定时间_IMM4";
CM_ SG_ 2332107943 CRC_M2I_Byrack_IMM4_23 "CRC校验_IMM4";
CM_ SG_ 2332107943 M2I_Byrack_HVS_IMM4_23 "绝缘测量电压_IMM4";
CM_ SG_ 2332107943 M2I_Byrack_Enable_IMM4_23 "绝缘采样使能位_IMM4";
CM_ SG_ 2332107943 M2I_Byrack_ReVeEnable_IMM4_23 "读取软件版本使能位_IMM4";
CM_ SG_ 2332107943 Reserved_23 "预留预留";
CM_ SG_ 2332107943 M2I_Byrack_IsPostTm_IMM4_23 "绝缘采样时间_IMM4";
CM_ SG_ 2332107943 M2I_Byrack_SysABStTm_IMM4_23 "电压稳定时间_IMM4";
CM_ SG_ 2332107944 CRC_M2I_Byrack_IMM4_24 "CRC校验_IMM4";
CM_ SG_ 2332107944 M2I_Byrack_HVS_IMM4_24 "绝缘测量电压_IMM4";
CM_ SG_ 2332107944 M2I_Byrack_Enable_IMM4_24 "绝缘采样使能位_IMM4";
CM_ SG_ 2332107944 M2I_Byrack_ReVeEnable_IMM4_24 "读取软件版本使能位_IMM4";
CM_ SG_ 2332107944 Reserved_24 "预留预留";
CM_ SG_ 2332107944 M2I_Byrack_IsPostTm_IMM4_24 "绝缘采样时间_IMM4";
CM_ SG_ 2332107944 M2I_Byrack_SysABStTm_IMM4_24 "电压稳定时间_IMM4";
CM_ SG_ 2332107945 CRC_M2I_Byrack_IMM4_25 "CRC校验_IMM4";
CM_ SG_ 2332107945 M2I_Byrack_HVS_IMM4_25 "绝缘测量电压_IMM4";
CM_ SG_ 2332107945 M2I_Byrack_Enable_IMM4_25 "绝缘采样使能位_IMM4";
CM_ SG_ 2332107945 M2I_Byrack_ReVeEnable_IMM4_25 "读取软件版本使能位_IMM4";
CM_ SG_ 2332107945 Reserved_25 "预留预留";
CM_ SG_ 2332107945 M2I_Byrack_IsPostTm_IMM4_25 "绝缘采样时间_IMM4";
CM_ SG_ 2332107945 M2I_Byrack_SysABStTm_IMM4_25 "电压稳定时间_IMM4";
CM_ SG_ 2332107946 CRC_M2I_Byrack_IMM4_26 "CRC校验_IMM4";
CM_ SG_ 2332107946 M2I_Byrack_HVS_IMM4_26 "绝缘测量电压_IMM4";
CM_ SG_ 2332107946 M2I_Byrack_Enable_IMM4_26 "绝缘采样使能位_IMM4";
CM_ SG_ 2332107946 M2I_Byrack_ReVeEnable_IMM4_26 "读取软件版本使能位_IMM4";
CM_ SG_ 2332107946 Reserved_26 "预留预留";
CM_ SG_ 2332107946 M2I_Byrack_IsPostTm_IMM4_26 "绝缘采样时间_IMM4";
CM_ SG_ 2332107946 M2I_Byrack_SysABStTm_IMM4_26 "电压稳定时间_IMM4";
CM_ SG_ 2332107947 CRC_M2I_Byrack_IMM4_27 "CRC校验_IMM4";
CM_ SG_ 2332107947 M2I_Byrack_HVS_IMM4_27 "绝缘测量电压_IMM4";
CM_ SG_ 2332107947 M2I_Byrack_Enable_IMM4_27 "绝缘采样使能位_IMM4";
CM_ SG_ 2332107947 M2I_Byrack_ReVeEnable_IMM4_27 "读取软件版本使能位_IMM4";
CM_ SG_ 2332107947 Reserved_27 "预留预留";
CM_ SG_ 2332107947 M2I_Byrack_IsPostTm_IMM4_27 "绝缘采样时间_IMM4";
CM_ SG_ 2332107947 M2I_Byrack_SysABStTm_IMM4_27 "电压稳定时间_IMM4";
CM_ SG_ 2332107948 CRC_M2I_Byrack_IMM4_28 "CRC校验_IMM4";
CM_ SG_ 2332107948 M2I_Byrack_HVS_IMM4_28 "绝缘测量电压_IMM4";
CM_ SG_ 2332107948 M2I_Byrack_Enable_IMM4_28 "绝缘采样使能位_IMM4";
CM_ SG_ 2332107948 M2I_Byrack_ReVeEnable_IMM4_28 "读取软件版本使能位_IMM4";
CM_ SG_ 2332107948 Reserved_28 "预留预留";
CM_ SG_ 2332107948 M2I_Byrack_IsPostTm_IMM4_28 "绝缘采样时间_IMM4";
CM_ SG_ 2332107948 M2I_Byrack_SysABStTm_IMM4_28 "电压稳定时间_IMM4";
CM_ SG_ 2332107949 CRC_M2I_Byrack_IMM4_29 "CRC校验_IMM4";
CM_ SG_ 2332107949 M2I_Byrack_HVS_IMM4_29 "绝缘测量电压_IMM4";
CM_ SG_ 2332107949 M2I_Byrack_Enable_IMM4_29 "绝缘采样使能位_IMM4";
CM_ SG_ 2332107949 M2I_Byrack_ReVeEnable_IMM4_29 "读取软件版本使能位_IMM4";
CM_ SG_ 2332107949 Reserved_29 "预留预留";
CM_ SG_ 2332107949 M2I_Byrack_IsPostTm_IMM4_29 "绝缘采样时间_IMM4";
CM_ SG_ 2332107949 M2I_Byrack_SysABStTm_IMM4_29 "电压稳定时间_IMM4";
CM_ SG_ 2332107950 CRC_M2I_Byrack_IMM4_30 "CRC校验_IMM4";
CM_ SG_ 2332107950 M2I_Byrack_HVS_IMM4_30 "绝缘测量电压_IMM4";
CM_ SG_ 2332107950 M2I_Byrack_Enable_IMM4_30 "绝缘采样使能位_IMM4";
CM_ SG_ 2332107950 M2I_Byrack_ReVeEnable_IMM4_30 "读取软件版本使能位_IMM4";
CM_ SG_ 2332107950 Reserved_30 "预留预留";
CM_ SG_ 2332107950 M2I_Byrack_IsPostTm_IMM4_30 "绝缘采样时间_IMM4";
CM_ SG_ 2332107950 M2I_Byrack_SysABStTm_IMM4_30 "电压稳定时间_IMM4";
CM_ SG_ 2332107951 CRC_M2I_Byrack_IMM4_31 "CRC校验_IMM4";
CM_ SG_ 2332107951 M2I_Byrack_HVS_IMM4_31 "绝缘测量电压_IMM4";
CM_ SG_ 2332107951 M2I_Byrack_Enable_IMM4_31 "绝缘采样使能位_IMM4";
CM_ SG_ 2332107951 M2I_Byrack_ReVeEnable_IMM4_31 "读取软件版本使能位_IMM4";
CM_ SG_ 2332107951 Reserved_31 "预留预留";
CM_ SG_ 2332107951 M2I_Byrack_IsPostTm_IMM4_31 "绝缘采样时间_IMM4";
CM_ SG_ 2332107951 M2I_Byrack_SysABStTm_IMM4_31 "电压稳定时间_IMM4";
CM_ SG_ 2332108177 CRC_M2I_Byrack_IMM5_01 "CRC校验_IMM5";
CM_ SG_ 2332108177 M2I_Byrack_HVS_IMM5_01 "绝缘测量电压_IMM5";
CM_ SG_ 2332108177 M2I_Byrack_Enable_IMM5_01 "绝缘采样使能位_IMM5";
CM_ SG_ 2332108177 M2I_Byrack_ReVeEnable_IMM5_01 "读取软件版本使能位_IMM5";
CM_ SG_ 2332108177 Reserved_01 "预留预留";
CM_ SG_ 2332108177 M2I_Byrack_IsPostTm_IMM5_01 "绝缘采样时间_IMM5";
CM_ SG_ 2332108177 M2I_Byrack_SysABStTm_IMM5_01 "电压稳定时间_IMM5";
CM_ SG_ 2332108178 CRC_M2I_Byrack_IMM5_02 "CRC校验_IMM5";
CM_ SG_ 2332108178 M2I_Byrack_HVS_IMM5_02 "绝缘测量电压_IMM5";
CM_ SG_ 2332108178 M2I_Byrack_Enable_IMM5_02 "绝缘采样使能位_IMM5";
CM_ SG_ 2332108178 M2I_Byrack_ReVeEnable_IMM5_02 "读取软件版本使能位_IMM5";
CM_ SG_ 2332108178 Reserved_02 "预留预留";
CM_ SG_ 2332108178 M2I_Byrack_IsPostTm_IMM5_02 "绝缘采样时间_IMM5";
CM_ SG_ 2332108178 M2I_Byrack_SysABStTm_IMM5_02 "电压稳定时间_IMM5";
CM_ SG_ 2332108179 CRC_M2I_Byrack_IMM5_03 "CRC校验_IMM5";
CM_ SG_ 2332108179 M2I_Byrack_HVS_IMM5_03 "绝缘测量电压_IMM5";
CM_ SG_ 2332108179 M2I_Byrack_Enable_IMM5_03 "绝缘采样使能位_IMM5";
CM_ SG_ 2332108179 M2I_Byrack_ReVeEnable_IMM5_03 "读取软件版本使能位_IMM5";
CM_ SG_ 2332108179 Reserved_03 "预留预留";
CM_ SG_ 2332108179 M2I_Byrack_IsPostTm_IMM5_03 "绝缘采样时间_IMM5";
CM_ SG_ 2332108179 M2I_Byrack_SysABStTm_IMM5_03 "电压稳定时间_IMM5";
CM_ SG_ 2332108180 CRC_M2I_Byrack_IMM5_04 "CRC校验_IMM5";
CM_ SG_ 2332108180 M2I_Byrack_HVS_IMM5_04 "绝缘测量电压_IMM5";
CM_ SG_ 2332108180 M2I_Byrack_Enable_IMM5_04 "绝缘采样使能位_IMM5";
CM_ SG_ 2332108180 M2I_Byrack_ReVeEnable_IMM5_04 "读取软件版本使能位_IMM5";
CM_ SG_ 2332108180 Reserved_04 "预留预留";
CM_ SG_ 2332108180 M2I_Byrack_IsPostTm_IMM5_04 "绝缘采样时间_IMM5";
CM_ SG_ 2332108180 M2I_Byrack_SysABStTm_IMM5_04 "电压稳定时间_IMM5";
CM_ SG_ 2332108181 CRC_M2I_Byrack_IMM5_05 "CRC校验_IMM5";
CM_ SG_ 2332108181 M2I_Byrack_HVS_IMM5_05 "绝缘测量电压_IMM5";
CM_ SG_ 2332108181 M2I_Byrack_Enable_IMM5_05 "绝缘采样使能位_IMM5";
CM_ SG_ 2332108181 M2I_Byrack_ReVeEnable_IMM5_05 "读取软件版本使能位_IMM5";
CM_ SG_ 2332108181 Reserved_05 "预留预留";
CM_ SG_ 2332108181 M2I_Byrack_IsPostTm_IMM5_05 "绝缘采样时间_IMM5";
CM_ SG_ 2332108181 M2I_Byrack_SysABStTm_IMM5_05 "电压稳定时间_IMM5";
CM_ SG_ 2332108182 CRC_M2I_Byrack_IMM5_06 "CRC校验_IMM5";
CM_ SG_ 2332108182 M2I_Byrack_HVS_IMM5_06 "绝缘测量电压_IMM5";
CM_ SG_ 2332108182 M2I_Byrack_Enable_IMM5_06 "绝缘采样使能位_IMM5";
CM_ SG_ 2332108182 M2I_Byrack_ReVeEnable_IMM5_06 "读取软件版本使能位_IMM5";
CM_ SG_ 2332108182 Reserved_06 "预留预留";
CM_ SG_ 2332108182 M2I_Byrack_IsPostTm_IMM5_06 "绝缘采样时间_IMM5";
CM_ SG_ 2332108182 M2I_Byrack_SysABStTm_IMM5_06 "电压稳定时间_IMM5";
CM_ SG_ 2332108183 CRC_M2I_Byrack_IMM5_07 "CRC校验_IMM5";
CM_ SG_ 2332108183 M2I_Byrack_HVS_IMM5_07 "绝缘测量电压_IMM5";
CM_ SG_ 2332108183 M2I_Byrack_Enable_IMM5_07 "绝缘采样使能位_IMM5";
CM_ SG_ 2332108183 M2I_Byrack_ReVeEnable_IMM5_07 "读取软件版本使能位_IMM5";
CM_ SG_ 2332108183 Reserved_07 "预留预留";
CM_ SG_ 2332108183 M2I_Byrack_IsPostTm_IMM5_07 "绝缘采样时间_IMM5";
CM_ SG_ 2332108183 M2I_Byrack_SysABStTm_IMM5_07 "电压稳定时间_IMM5";
CM_ SG_ 2332108184 CRC_M2I_Byrack_IMM5_08 "CRC校验_IMM5";
CM_ SG_ 2332108184 M2I_Byrack_HVS_IMM5_08 "绝缘测量电压_IMM5";
CM_ SG_ 2332108184 M2I_Byrack_Enable_IMM5_08 "绝缘采样使能位_IMM5";
CM_ SG_ 2332108184 M2I_Byrack_ReVeEnable_IMM5_08 "读取软件版本使能位_IMM5";
CM_ SG_ 2332108184 Reserved_08 "预留预留";
CM_ SG_ 2332108184 M2I_Byrack_IsPostTm_IMM5_08 "绝缘采样时间_IMM5";
CM_ SG_ 2332108184 M2I_Byrack_SysABStTm_IMM5_08 "电压稳定时间_IMM5";
CM_ SG_ 2332108185 CRC_M2I_Byrack_IMM5_09 "CRC校验_IMM5";
CM_ SG_ 2332108185 M2I_Byrack_HVS_IMM5_09 "绝缘测量电压_IMM5";
CM_ SG_ 2332108185 M2I_Byrack_Enable_IMM5_09 "绝缘采样使能位_IMM5";
CM_ SG_ 2332108185 M2I_Byrack_ReVeEnable_IMM5_09 "读取软件版本使能位_IMM5";
CM_ SG_ 2332108185 Reserved_09 "预留预留";
CM_ SG_ 2332108185 M2I_Byrack_IsPostTm_IMM5_09 "绝缘采样时间_IMM5";
CM_ SG_ 2332108185 M2I_Byrack_SysABStTm_IMM5_09 "电压稳定时间_IMM5";
CM_ SG_ 2332108186 CRC_M2I_Byrack_IMM5_10 "CRC校验_IMM5";
CM_ SG_ 2332108186 M2I_Byrack_HVS_IMM5_10 "绝缘测量电压_IMM5";
CM_ SG_ 2332108186 M2I_Byrack_Enable_IMM5_10 "绝缘采样使能位_IMM5";
CM_ SG_ 2332108186 M2I_Byrack_ReVeEnable_IMM5_10 "读取软件版本使能位_IMM5";
CM_ SG_ 2332108186 Reserved_10 "预留预留";
CM_ SG_ 2332108186 M2I_Byrack_IsPostTm_IMM5_10 "绝缘采样时间_IMM5";
CM_ SG_ 2332108186 M2I_Byrack_SysABStTm_IMM5_10 "电压稳定时间_IMM5";
CM_ SG_ 2332108187 CRC_M2I_Byrack_IMM5_11 "CRC校验_IMM5";
CM_ SG_ 2332108187 M2I_Byrack_HVS_IMM5_11 "绝缘测量电压_IMM5";
CM_ SG_ 2332108187 M2I_Byrack_Enable_IMM5_11 "绝缘采样使能位_IMM5";
CM_ SG_ 2332108187 M2I_Byrack_ReVeEnable_IMM5_11 "读取软件版本使能位_IMM5";
CM_ SG_ 2332108187 Reserved_11 "预留预留";
CM_ SG_ 2332108187 M2I_Byrack_IsPostTm_IMM5_11 "绝缘采样时间_IMM5";
CM_ SG_ 2332108187 M2I_Byrack_SysABStTm_IMM5_11 "电压稳定时间_IMM5";
CM_ SG_ 2332108188 CRC_M2I_Byrack_IMM5_12 "CRC校验_IMM5";
CM_ SG_ 2332108188 M2I_Byrack_HVS_IMM5_12 "绝缘测量电压_IMM5";
CM_ SG_ 2332108188 M2I_Byrack_Enable_IMM5_12 "绝缘采样使能位_IMM5";
CM_ SG_ 2332108188 M2I_Byrack_ReVeEnable_IMM5_12 "读取软件版本使能位_IMM5";
CM_ SG_ 2332108188 Reserved_12 "预留预留";
CM_ SG_ 2332108188 M2I_Byrack_IsPostTm_IMM5_12 "绝缘采样时间_IMM5";
CM_ SG_ 2332108188 M2I_Byrack_SysABStTm_IMM5_12 "电压稳定时间_IMM5";
CM_ SG_ 2332108189 CRC_M2I_Byrack_IMM5_13 "CRC校验_IMM5";
CM_ SG_ 2332108189 M2I_Byrack_HVS_IMM5_13 "绝缘测量电压_IMM5";
CM_ SG_ 2332108189 M2I_Byrack_Enable_IMM5_13 "绝缘采样使能位_IMM5";
CM_ SG_ 2332108189 M2I_Byrack_ReVeEnable_IMM5_13 "读取软件版本使能位_IMM5";
CM_ SG_ 2332108189 Reserved_13 "预留预留";
CM_ SG_ 2332108189 M2I_Byrack_IsPostTm_IMM5_13 "绝缘采样时间_IMM5";
CM_ SG_ 2332108189 M2I_Byrack_SysABStTm_IMM5_13 "电压稳定时间_IMM5";
CM_ SG_ 2332108190 CRC_M2I_Byrack_IMM5_14 "CRC校验_IMM5";
CM_ SG_ 2332108190 M2I_Byrack_HVS_IMM5_14 "绝缘测量电压_IMM5";
CM_ SG_ 2332108190 M2I_Byrack_Enable_IMM5_14 "绝缘采样使能位_IMM5";
CM_ SG_ 2332108190 M2I_Byrack_ReVeEnable_IMM5_14 "读取软件版本使能位_IMM5";
CM_ SG_ 2332108190 Reserved_14 "预留预留";
CM_ SG_ 2332108190 M2I_Byrack_IsPostTm_IMM5_14 "绝缘采样时间_IMM5";
CM_ SG_ 2332108190 M2I_Byrack_SysABStTm_IMM5_14 "电压稳定时间_IMM5";
VAL_ 2332155942 I2A_Byrack_VoltVld_06 0 "invalid" 1 "Valid" ;
VAL_ 2332155942 I2A_Byrack_VoltErr_06 0 "normal" 1 "error" ;
VAL_ 2332155942 I2A_Byrack_InsResValid_06 0 "invalid" 1 "Valid" ;
VAL_ 2332155942 I2A_Byrack_IsoResPos_06 0 "invalid" 1 "Valid" 2 "Init" ;
VAL_ 2332155943 I2A_Byrack_VoltVld_07 0 "invalid" 1 "Valid" ;
VAL_ 2332155943 I2A_Byrack_VoltErr_07 0 "normal" 1 "error" ;
VAL_ 2332155943 I2A_Byrack_InsResValid_07 0 "invalid" 1 "Valid" ;
VAL_ 2332155943 I2A_Byrack_IsoResPos_07 0 "invalid" 1 "Valid" 2 "Init" ;
VAL_ 2332155944 I2A_Byrack_VoltVld_08 0 "invalid" 1 "Valid" ;
VAL_ 2332155944 I2A_Byrack_VoltErr_08 0 "normal" 1 "error" ;
VAL_ 2332155944 I2A_Byrack_InsResValid_08 0 "invalid" 1 "Valid" ;
VAL_ 2332155944 I2A_Byrack_IsoResPos_08 0 "invalid" 1 "Valid" 2 "Init" ;
VAL_ 2332155945 I2A_Byrack_VoltVld_09 0 "invalid" 1 "Valid" ;
VAL_ 2332155945 I2A_Byrack_VoltErr_09 0 "normal" 1 "error" ;
VAL_ 2332155945 I2A_Byrack_InsResValid_09 0 "invalid" 1 "Valid" ;
VAL_ 2332155945 I2A_Byrack_IsoResPos_09 0 "invalid" 1 "Valid" 2 "Init" ;
VAL_ 2332155946 I2A_Byrack_VoltVld_10 0 "invalid" 1 "Valid" ;
VAL_ 2332155946 I2A_Byrack_VoltErr_10 0 "normal" 1 "error" ;
VAL_ 2332155946 I2A_Byrack_InsResValid_10 0 "invalid" 1 "Valid" ;
VAL_ 2332155946 I2A_Byrack_IsoResPos_10 0 "invalid" 1 "Valid" 2 "Init" ;
VAL_ 2332155947 I2A_Byrack_VoltVld_11 0 "invalid" 1 "Valid" ;
VAL_ 2332155947 I2A_Byrack_VoltErr_11 0 "normal" 1 "error" ;
VAL_ 2332155947 I2A_Byrack_InsResValid_11 0 "invalid" 1 "Valid" ;
VAL_ 2332155947 I2A_Byrack_IsoResPos_11 0 "invalid" 1 "Valid" 2 "Init" ;
VAL_ 2332155948 I2A_Byrack_VoltVld_12 0 "invalid" 1 "Valid" ;
VAL_ 2332155948 I2A_Byrack_VoltErr_12 0 "normal" 1 "error" ;
VAL_ 2332155948 I2A_Byrack_InsResValid_12 0 "invalid" 1 "Valid" ;
VAL_ 2332155948 I2A_Byrack_IsoResPos_12 0 "invalid" 1 "Valid" 2 "Init" ;
VAL_ 2332155949 I2A_Byrack_VoltVld_13 0 "invalid" 1 "Valid" ;
VAL_ 2332155949 I2A_Byrack_VoltErr_13 0 "normal" 1 "error" ;
VAL_ 2332155949 I2A_Byrack_InsResValid_13 0 "invalid" 1 "Valid" ;
VAL_ 2332155949 I2A_Byrack_IsoResPos_13 0 "invalid" 1 "Valid" 2 "Init" ;
VAL_ 2332155950 I2A_Byrack_VoltVld_14 0 "invalid" 1 "Valid" ;
VAL_ 2332155950 I2A_Byrack_VoltErr_14 0 "normal" 1 "error" ;
VAL_ 2332155950 I2A_Byrack_InsResValid_14 0 "invalid" 1 "Valid" ;
VAL_ 2332155950 I2A_Byrack_IsoResPos_14 0 "invalid" 1 "Valid" 2 "Init" ;
VAL_ 2332155951 I2A_Byrack_VoltVld_15 0 "invalid" 1 "Valid" ;
VAL_ 2332155951 I2A_Byrack_VoltErr_15 0 "normal" 1 "error" ;
VAL_ 2332155951 I2A_Byrack_InsResValid_15 0 "invalid" 1 "Valid" ;
VAL_ 2332155951 I2A_Byrack_IsoResPos_15 0 "invalid" 1 "Valid" 2 "Init" ;
VAL_ 2332155952 I2A_Byrack_VoltVld_16 0 "invalid" 1 "Valid" ;
VAL_ 2332155952 I2A_Byrack_VoltErr_16 0 "normal" 1 "error" ;
VAL_ 2332155952 I2A_Byrack_InsResValid_16 0 "invalid" 1 "Valid" ;
VAL_ 2332155952 I2A_Byrack_IsoResPos_16 0 "invalid" 1 "Valid" 2 "Init" ;
VAL_ 2332155953 I2A_Byrack_VoltVld_17 0 "invalid" 1 "Valid" ;
VAL_ 2332155953 I2A_Byrack_VoltErr_17 0 "normal" 1 "error" ;
VAL_ 2332155953 I2A_Byrack_InsResValid_17 0 "invalid" 1 "Valid" ;
VAL_ 2332155953 I2A_Byrack_IsoResPos_17 0 "invalid" 1 "Valid" 2 "Init" ;
VAL_ 2332155954 I2A_Byrack_VoltVld_18 0 "invalid" 1 "Valid" ;
VAL_ 2332155954 I2A_Byrack_VoltErr_18 0 "normal" 1 "error" ;
VAL_ 2332155954 I2A_Byrack_InsResValid_18 0 "invalid" 1 "Valid" ;
VAL_ 2332155954 I2A_Byrack_IsoResPos_18 0 "invalid" 1 "Valid" 2 "Init" ;
VAL_ 2332155955 I2A_Byrack_VoltVld_19 0 "invalid" 1 "Valid" ;
VAL_ 2332155955 I2A_Byrack_VoltErr_19 0 "normal" 1 "error" ;
VAL_ 2332155955 I2A_Byrack_InsResValid_19 0 "invalid" 1 "Valid" ;
VAL_ 2332155955 I2A_Byrack_IsoResPos_19 0 "invalid" 1 "Valid" 2 "Init" ;
VAL_ 2332155956 I2A_Byrack_VoltVld_20 0 "invalid" 1 "Valid" ;
VAL_ 2332155956 I2A_Byrack_VoltErr_20 0 "normal" 1 "error" ;
VAL_ 2332155956 I2A_Byrack_InsResValid_20 0 "invalid" 1 "Valid" ;
VAL_ 2332155956 I2A_Byrack_IsoResPos_20 0 "invalid" 1 "Valid" 2 "Init" ;
VAL_ 2332155957 I2A_Byrack_VoltVld_21 0 "invalid" 1 "Valid" ;
VAL_ 2332155957 I2A_Byrack_VoltErr_21 0 "normal" 1 "error" ;
VAL_ 2332155957 I2A_Byrack_InsResValid_21 0 "invalid" 1 "Valid" ;
VAL_ 2332155957 I2A_Byrack_IsoResPos_21 0 "invalid" 1 "Valid" 2 "Init" ;
VAL_ 2332155958 I2A_Byrack_VoltVld_22 0 "invalid" 1 "Valid" ;
VAL_ 2332155958 I2A_Byrack_VoltErr_22 0 "normal" 1 "error" ;
VAL_ 2332155958 I2A_Byrack_InsResValid_22 0 "invalid" 1 "Valid" ;
VAL_ 2332155958 I2A_Byrack_IsoResPos_22 0 "invalid" 1 "Valid" 2 "Init" ;
VAL_ 2332155959 I2A_Byrack_VoltVld_23 0 "invalid" 1 "Valid" ;
VAL_ 2332155959 I2A_Byrack_VoltErr_23 0 "normal" 1 "error" ;
VAL_ 2332155959 I2A_Byrack_InsResValid_23 0 "invalid" 1 "Valid" ;
VAL_ 2332155959 I2A_Byrack_IsoResPos_23 0 "invalid" 1 "Valid" 2 "Init" ;
VAL_ 2332155960 I2A_Byrack_VoltVld_24 0 "invalid" 1 "Valid" ;
VAL_ 2332155960 I2A_Byrack_VoltErr_24 0 "normal" 1 "error" ;
VAL_ 2332155960 I2A_Byrack_InsResValid_24 0 "invalid" 1 "Valid" ;
VAL_ 2332155960 I2A_Byrack_IsoResPos_24 0 "invalid" 1 "Valid" 2 "Init" ;
VAL_ 2332155961 I2A_Byrack_VoltVld_25 0 "invalid" 1 "Valid" ;
VAL_ 2332155961 I2A_Byrack_VoltErr_25 0 "normal" 1 "error" ;
VAL_ 2332155961 I2A_Byrack_InsResValid_25 0 "invalid" 1 "Valid" ;
VAL_ 2332155961 I2A_Byrack_IsoResPos_25 0 "invalid" 1 "Valid" 2 "Init" ;
VAL_ 2332155962 I2A_Byrack_VoltVld_26 0 "invalid" 1 "Valid" ;
VAL_ 2332155962 I2A_Byrack_VoltErr_26 0 "normal" 1 "error" ;
VAL_ 2332155962 I2A_Byrack_InsResValid_26 0 "invalid" 1 "Valid" ;
VAL_ 2332155962 I2A_Byrack_IsoResPos_26 0 "invalid" 1 "Valid" 2 "Init" ;
VAL_ 2332155963 I2A_Byrack_VoltVld_27 0 "invalid" 1 "Valid" ;
VAL_ 2332155963 I2A_Byrack_VoltErr_27 0 "normal" 1 "error" ;
VAL_ 2332155963 I2A_Byrack_InsResValid_27 0 "invalid" 1 "Valid" ;
VAL_ 2332155963 I2A_Byrack_IsoResPos_27 0 "invalid" 1 "Valid" 2 "Init" ;
VAL_ 2332155964 I2A_Byrack_VoltVld_28 0 "invalid" 1 "Valid" ;
VAL_ 2332155964 I2A_Byrack_VoltErr_28 0 "normal" 1 "error" ;
VAL_ 2332155964 I2A_Byrack_InsResValid_28 0 "invalid" 1 "Valid" ;
VAL_ 2332155964 I2A_Byrack_IsoResPos_28 0 "invalid" 1 "Valid" 2 "Init" ;
VAL_ 2332155965 I2A_Byrack_VoltVld_29 0 "invalid" 1 "Valid" ;
VAL_ 2332155965 I2A_Byrack_VoltErr_29 0 "normal" 1 "error" ;
VAL_ 2332155965 I2A_Byrack_InsResValid_29 0 "invalid" 1 "Valid" ;
VAL_ 2332155965 I2A_Byrack_IsoResPos_29 0 "invalid" 1 "Valid" 2 "Init" ;
VAL_ 2332155966 I2A_Byrack_VoltVld_30 0 "invalid" 1 "Valid" ;
VAL_ 2332155966 I2A_Byrack_VoltErr_30 0 "normal" 1 "error" ;
VAL_ 2332155966 I2A_Byrack_InsResValid_30 0 "invalid" 1 "Valid" ;
VAL_ 2332155966 I2A_Byrack_IsoResPos_30 0 "invalid" 1 "Valid" 2 "Init" ;
VAL_ 2332155967 I2A_Byrack_VoltVld_31 0 "invalid" 1 "Valid" ;
VAL_ 2332155967 I2A_Byrack_VoltErr_31 0 "normal" 1 "error" ;
VAL_ 2332155967 I2A_Byrack_InsResValid_31 0 "invalid" 1 "Valid" ;
VAL_ 2332155967 I2A_Byrack_IsoResPos_31 0 "invalid" 1 "Valid" 2 "Init" ;
VAL_ 2332107153 M2I_Byrack_Enable_IMM1_01 1 "Deactive" 2 "Active" ;
VAL_ 2332107153 M2I_Byrack_ReVeEnable_IMM1_01 0 "invalid" 1 "Read SW-Version" 2 "Read HW-Version" 3 "Barcode" ;
VAL_ 2332107154 M2I_Byrack_Enable_IMM1_02 1 "Deactive" 2 "Active" ;
VAL_ 2332107154 M2I_Byrack_ReVeEnable_IMM1_02 0 "invalid" 1 "Read SW-Version" 2 "Read HW-Version" 3 "Barcode" ;
VAL_ 2332107155 M2I_Byrack_Enable_IMM1_03 1 "Deactive" 2 "Active" ;
VAL_ 2332107155 M2I_Byrack_ReVeEnable_IMM1_03 0 "invalid" 1 "Read SW-Version" 2 "Read HW-Version" 3 "Barcode" ;
VAL_ 2332107156 M2I_Byrack_Enable_IMM1_04 1 "Deactive" 2 "Active" ;
VAL_ 2332107156 M2I_Byrack_ReVeEnable_IMM1_04 0 "invalid" 1 "Read SW-Version" 2 "Read HW-Version" 3 "Barcode" ;
VAL_ 2332107157 M2I_Byrack_Enable_IMM1_05 1 "Deactive" 2 "Active" ;
VAL_ 2332107157 M2I_Byrack_ReVeEnable_IMM1_05 0 "invalid" 1 "Read SW-Version" 2 "Read HW-Version" 3 "Barcode" ;
VAL_ 2332107158 M2I_Byrack_Enable_IMM1_06 1 "Deactive" 2 "Active" ;
VAL_ 2332107158 M2I_Byrack_ReVeEnable_IMM1_06 0 "invalid" 1 "Read SW-Version" 2 "Read HW-Version" 3 "Barcode" ;
VAL_ 2332107159 M2I_Byrack_Enable_IMM1_07 1 "Deactive" 2 "Active" ;
VAL_ 2332107159 M2I_Byrack_ReVeEnable_IMM1_07 0 "invalid" 1 "Read SW-Version" 2 "Read HW-Version" 3 "Barcode" ;
VAL_ 2332107160 M2I_Byrack_Enable_IMM1_08 1 "Deactive" 2 "Active" ;
VAL_ 2332107160 M2I_Byrack_ReVeEnable_IMM1_08 0 "invalid" 1 "Read SW-Version" 2 "Read HW-Version" 3 "Barcode" ;
VAL_ 2332107161 M2I_Byrack_Enable_IMM1_09 1 "Deactive" 2 "Active" ;
VAL_ 2332107161 M2I_Byrack_ReVeEnable_IMM1_09 0 "invalid" 1 "Read SW-Version" 2 "Read HW-Version" 3 "Barcode" ;
VAL_ 2332107162 M2I_Byrack_Enable_IMM1_10 1 "Deactive" 2 "Active" ;
VAL_ 2332107162 M2I_Byrack_ReVeEnable_IMM1_10 0 "invalid" 1 "Read SW-Version" 2 "Read HW-Version" 3 "Barcode" ;
VAL_ 2332107163 M2I_Byrack_Enable_IMM1_11 1 "Deactive" 2 "Active" ;
VAL_ 2332107163 M2I_Byrack_ReVeEnable_IMM1_11 0 "invalid" 1 "Read SW-Version" 2 "Read HW-Version" 3 "Barcode" ;
VAL_ 2332107164 M2I_Byrack_Enable_IMM1_12 1 "Deactive" 2 "Active" ;
VAL_ 2332107164 M2I_Byrack_ReVeEnable_IMM1_12 0 "invalid" 1 "Read SW-Version" 2 "Read HW-Version" 3 "Barcode" ;
VAL_ 2332107165 M2I_Byrack_Enable_IMM1_13 1 "Deactive" 2 "Active" ;
VAL_ 2332107165 M2I_Byrack_ReVeEnable_IMM1_13 0 "invalid" 1 "Read SW-Version" 2 "Read HW-Version" 3 "Barcode" ;
VAL_ 2332107166 M2I_Byrack_Enable_IMM1_14 1 "Deactive" 2 "Active" ;
VAL_ 2332107166 M2I_Byrack_ReVeEnable_IMM1_14 0 "invalid" 1 "Read SW-Version" 2 "Read HW-Version" 3 "Barcode" ;
VAL_ 2332107167 M2I_Byrack_Enable_IMM1_15 1 "Deactive" 2 "Active" ;
VAL_ 2332107167 M2I_Byrack_ReVeEnable_IMM1_15 0 "invalid" 1 "Read SW-Version" 2 "Read HW-Version" 3 "Barcode" ;
VAL_ 2332107168 M2I_Byrack_Enable_IMM1_16 1 "Deactive" 2 "Active" ;
VAL_ 2332107168 M2I_Byrack_ReVeEnable_IMM1_16 0 "invalid" 1 "Read SW-Version" 2 "Read HW-Version" 3 "Barcode" ;
VAL_ 2332107169 M2I_Byrack_Enable_IMM1_17 1 "Deactive" 2 "Active" ;
VAL_ 2332107169 M2I_Byrack_ReVeEnable_IMM1_17 0 "invalid" 1 "Read SW-Version" 2 "Read HW-Version" 3 "Barcode" ;
VAL_ 2332107170 M2I_Byrack_Enable_IMM1_18 1 "Deactive" 2 "Active" ;
VAL_ 2332107170 M2I_Byrack_ReVeEnable_IMM1_18 0 "invalid" 1 "Read SW-Version" 2 "Read HW-Version" 3 "Barcode" ;
VAL_ 2332107171 M2I_Byrack_Enable_IMM1_19 1 "Deactive" 2 "Active" ;
VAL_ 2332107171 M2I_Byrack_ReVeEnable_IMM1_19 0 "invalid" 1 "Read SW-Version" 2 "Read HW-Version" 3 "Barcode" ;
VAL_ 2332107172 M2I_Byrack_Enable_IMM1_20 1 "Deactive" 2 "Active" ;
VAL_ 2332107172 M2I_Byrack_ReVeEnable_IMM1_20 0 "invalid" 1 "Read SW-Version" 2 "Read HW-Version" 3 "Barcode" ;
VAL_ 2332107173 M2I_Byrack_Enable_IMM1_21 1 "Deactive" 2 "Active" ;
VAL_ 2332107173 M2I_Byrack_ReVeEnable_IMM1_21 0 "invalid" 1 "Read SW-Version" 2 "Read HW-Version" 3 "Barcode" ;
VAL_ 2332107174 M2I_Byrack_Enable_IMM1_22 1 "Deactive" 2 "Active" ;
VAL_ 2332107174 M2I_Byrack_ReVeEnable_IMM1_22 0 "invalid" 1 "Read SW-Version" 2 "Read HW-Version" 3 "Barcode" ;
VAL_ 2332107175 M2I_Byrack_Enable_IMM1_23 1 "Deactive" 2 "Active" ;
VAL_ 2332107175 M2I_Byrack_ReVeEnable_IMM1_23 0 "invalid" 1 "Read SW-Version" 2 "Read HW-Version" 3 "Barcode" ;
VAL_ 2332107176 M2I_Byrack_Enable_IMM1_24 1 "Deactive" 2 "Active" ;
VAL_ 2332107176 M2I_Byrack_ReVeEnable_IMM1_24 0 "invalid" 1 "Read SW-Version" 2 "Read HW-Version" 3 "Barcode" ;
VAL_ 2332107177 M2I_Byrack_Enable_IMM1_25 1 "Deactive" 2 "Active" ;
VAL_ 2332107177 M2I_Byrack_ReVeEnable_IMM1_25 0 "invalid" 1 "Read SW-Version" 2 "Read HW-Version" 3 "Barcode" ;
VAL_ 2332107178 M2I_Byrack_Enable_IMM1_26 1 "Deactive" 2 "Active" ;
VAL_ 2332107178 M2I_Byrack_ReVeEnable_IMM1_26 0 "invalid" 1 "Read SW-Version" 2 "Read HW-Version" 3 "Barcode" ;
VAL_ 2332107179 M2I_Byrack_Enable_IMM1_27 1 "Deactive" 2 "Active" ;
VAL_ 2332107179 M2I_Byrack_ReVeEnable_IMM1_27 0 "invalid" 1 "Read SW-Version" 2 "Read HW-Version" 3 "Barcode" ;
VAL_ 2332107180 M2I_Byrack_Enable_IMM1_28 1 "Deactive" 2 "Active" ;
VAL_ 2332107180 M2I_Byrack_ReVeEnable_IMM1_28 0 "invalid" 1 "Read SW-Version" 2 "Read HW-Version" 3 "Barcode" ;
VAL_ 2332107181 M2I_Byrack_Enable_IMM1_29 1 "Deactive" 2 "Active" ;
VAL_ 2332107181 M2I_Byrack_ReVeEnable_IMM1_29 0 "invalid" 1 "Read SW-Version" 2 "Read HW-Version" 3 "Barcode" ;
VAL_ 2332107182 M2I_Byrack_Enable_IMM1_30 1 "Deactive" 2 "Active" ;
VAL_ 2332107182 M2I_Byrack_ReVeEnable_IMM1_30 0 "invalid" 1 "Read SW-Version" 2 "Read HW-Version" 3 "Barcode" ;
VAL_ 2332107183 M2I_Byrack_Enable_IMM1_31 1 "Deactive" 2 "Active" ;
VAL_ 2332107183 M2I_Byrack_ReVeEnable_IMM1_31 0 "invalid" 1 "Read SW-Version" 2 "Read HW-Version" 3 "Barcode" ;
VAL_ 2332107409 M2I_Byrack_Enable_IMM2_01 1 "Deactive" 2 "Active" ;
VAL_ 2332107409 M2I_Byrack_ReVeEnable_IMM2_01 0 "invalid" 1 "Read SW-Version" 2 "Read HW-Version" 3 "Barcode" ;
VAL_ 2332107410 M2I_Byrack_Enable_IMM2_02 1 "Deactive" 2 "Active" ;
VAL_ 2332107410 M2I_Byrack_ReVeEnable_IMM2_02 0 "invalid" 1 "Read SW-Version" 2 "Read HW-Version" 3 "Barcode" ;
VAL_ 2332107411 M2I_Byrack_Enable_IMM2_03 1 "Deactive" 2 "Active" ;
VAL_ 2332107411 M2I_Byrack_ReVeEnable_IMM2_03 0 "invalid" 1 "Read SW-Version" 2 "Read HW-Version" 3 "Barcode" ;
VAL_ 2332107412 M2I_Byrack_Enable_IMM2_04 1 "Deactive" 2 "Active" ;
VAL_ 2332107412 M2I_Byrack_ReVeEnable_IMM2_04 0 "invalid" 1 "Read SW-Version" 2 "Read HW-Version" 3 "Barcode" ;
VAL_ 2332107413 M2I_Byrack_Enable_IMM2_05 1 "Deactive" 2 "Active" ;
VAL_ 2332107413 M2I_Byrack_ReVeEnable_IMM2_05 0 "invalid" 1 "Read SW-Version" 2 "Read HW-Version" 3 "Barcode" ;
VAL_ 2332107414 M2I_Byrack_Enable_IMM2_06 1 "Deactive" 2 "Active" ;
VAL_ 2332107414 M2I_Byrack_ReVeEnable_IMM2_06 0 "invalid" 1 "Read SW-Version" 2 "Read HW-Version" 3 "Barcode" ;
VAL_ 2332107415 M2I_Byrack_Enable_IMM2_07 1 "Deactive" 2 "Active" ;
VAL_ 2332107415 M2I_Byrack_ReVeEnable_IMM2_07 0 "invalid" 1 "Read SW-Version" 2 "Read HW-Version" 3 "Barcode" ;
VAL_ 2332107416 M2I_Byrack_Enable_IMM2_08 1 "Deactive" 2 "Active" ;
VAL_ 2332107416 M2I_Byrack_ReVeEnable_IMM2_08 0 "invalid" 1 "Read SW-Version" 2 "Read HW-Version" 3 "Barcode" ;
VAL_ 2332107417 M2I_Byrack_Enable_IMM2_09 1 "Deactive" 2 "Active" ;
VAL_ 2332107417 M2I_Byrack_ReVeEnable_IMM2_09 0 "invalid" 1 "Read SW-Version" 2 "Read HW-Version" 3 "Barcode" ;
VAL_ 2332107418 M2I_Byrack_Enable_IMM2_10 1 "Deactive" 2 "Active" ;
VAL_ 2332107418 M2I_Byrack_ReVeEnable_IMM2_10 0 "invalid" 1 "Read SW-Version" 2 "Read HW-Version" 3 "Barcode" ;
VAL_ 2332107419 M2I_Byrack_Enable_IMM2_11 1 "Deactive" 2 "Active" ;
VAL_ 2332107419 M2I_Byrack_ReVeEnable_IMM2_11 0 "invalid" 1 "Read SW-Version" 2 "Read HW-Version" 3 "Barcode" ;
VAL_ 2332107420 M2I_Byrack_Enable_IMM2_12 1 "Deactive" 2 "Active" ;
VAL_ 2332107420 M2I_Byrack_ReVeEnable_IMM2_12 0 "invalid" 1 "Read SW-Version" 2 "Read HW-Version" 3 "Barcode" ;
VAL_ 2332107421 M2I_Byrack_Enable_IMM2_13 1 "Deactive" 2 "Active" ;
VAL_ 2332107421 M2I_Byrack_ReVeEnable_IMM2_13 0 "invalid" 1 "Read SW-Version" 2 "Read HW-Version" 3 "Barcode" ;
VAL_ 2332107422 M2I_Byrack_Enable_IMM2_14 1 "Deactive" 2 "Active" ;
VAL_ 2332107422 M2I_Byrack_ReVeEnable_IMM2_14 0 "invalid" 1 "Read SW-Version" 2 "Read HW-Version" 3 "Barcode" ;
VAL_ 2332107423 M2I_Byrack_Enable_IMM2_15 1 "Deactive" 2 "Active" ;
VAL_ 2332107423 M2I_Byrack_ReVeEnable_IMM2_15 0 "invalid" 1 "Read SW-Version" 2 "Read HW-Version" 3 "Barcode" ;
VAL_ 2332107424 M2I_Byrack_Enable_IMM2_16 1 "Deactive" 2 "Active" ;
VAL_ 2332107424 M2I_Byrack_ReVeEnable_IMM2_16 0 "invalid" 1 "Read SW-Version" 2 "Read HW-Version" 3 "Barcode" ;
VAL_ 2332107425 M2I_Byrack_Enable_IMM2_17 1 "Deactive" 2 "Active" ;
VAL_ 2332107425 M2I_Byrack_ReVeEnable_IMM2_17 0 "invalid" 1 "Read SW-Version" 2 "Read HW-Version" 3 "Barcode" ;
VAL_ 2332107426 M2I_Byrack_Enable_IMM2_18 1 "Deactive" 2 "Active" ;
VAL_ 2332107426 M2I_Byrack_ReVeEnable_IMM2_18 0 "invalid" 1 "Read SW-Version" 2 "Read HW-Version" 3 "Barcode" ;
VAL_ 2332107427 M2I_Byrack_Enable_IMM2_19 1 "Deactive" 2 "Active" ;
VAL_ 2332107427 M2I_Byrack_ReVeEnable_IMM2_19 0 "invalid" 1 "Read SW-Version" 2 "Read HW-Version" 3 "Barcode" ;
VAL_ 2332107428 M2I_Byrack_Enable_IMM2_20 1 "Deactive" 2 "Active" ;
VAL_ 2332107428 M2I_Byrack_ReVeEnable_IMM2_20 0 "invalid" 1 "Read SW-Version" 2 "Read HW-Version" 3 "Barcode" ;
VAL_ 2332107429 M2I_Byrack_Enable_IMM2_21 1 "Deactive" 2 "Active" ;
VAL_ 2332107429 M2I_Byrack_ReVeEnable_IMM2_21 0 "invalid" 1 "Read SW-Version" 2 "Read HW-Version" 3 "Barcode" ;
VAL_ 2332107430 M2I_Byrack_Enable_IMM2_22 1 "Deactive" 2 "Active" ;
VAL_ 2332107430 M2I_Byrack_ReVeEnable_IMM2_22 0 "invalid" 1 "Read SW-Version" 2 "Read HW-Version" 3 "Barcode" ;
VAL_ 2332107431 M2I_Byrack_Enable_IMM2_23 1 "Deactive" 2 "Active" ;
VAL_ 2332107431 M2I_Byrack_ReVeEnable_IMM2_23 0 "invalid" 1 "Read SW-Version" 2 "Read HW-Version" 3 "Barcode" ;
VAL_ 2332107432 M2I_Byrack_Enable_IMM2_24 1 "Deactive" 2 "Active" ;
VAL_ 2332107432 M2I_Byrack_ReVeEnable_IMM2_24 0 "invalid" 1 "Read SW-Version" 2 "Read HW-Version" 3 "Barcode" ;
VAL_ 2332107433 M2I_Byrack_Enable_IMM2_25 1 "Deactive" 2 "Active" ;
VAL_ 2332107433 M2I_Byrack_ReVeEnable_IMM2_25 0 "invalid" 1 "Read SW-Version" 2 "Read HW-Version" 3 "Barcode" ;
VAL_ 2332107434 M2I_Byrack_Enable_IMM2_26 1 "Deactive" 2 "Active" ;
VAL_ 2332107434 M2I_Byrack_ReVeEnable_IMM2_26 0 "invalid" 1 "Read SW-Version" 2 "Read HW-Version" 3 "Barcode" ;
VAL_ 2332107435 M2I_Byrack_Enable_IMM2_27 1 "Deactive" 2 "Active" ;
VAL_ 2332107435 M2I_Byrack_ReVeEnable_IMM2_27 0 "invalid" 1 "Read SW-Version" 2 "Read HW-Version" 3 "Barcode" ;
VAL_ 2332107436 M2I_Byrack_Enable_IMM2_28 1 "Deactive" 2 "Active" ;
VAL_ 2332107436 M2I_Byrack_ReVeEnable_IMM2_28 0 "invalid" 1 "Read SW-Version" 2 "Read HW-Version" 3 "Barcode" ;
VAL_ 2332107437 M2I_Byrack_Enable_IMM2_29 1 "Deactive" 2 "Active" ;
VAL_ 2332107437 M2I_Byrack_ReVeEnable_IMM2_29 0 "invalid" 1 "Read SW-Version" 2 "Read HW-Version" 3 "Barcode" ;
VAL_ 2332107438 M2I_Byrack_Enable_IMM2_30 1 "Deactive" 2 "Active" ;
VAL_ 2332107438 M2I_Byrack_ReVeEnable_IMM2_30 0 "invalid" 1 "Read SW-Version" 2 "Read HW-Version" 3 "Barcode" ;
VAL_ 2332107439 M2I_Byrack_Enable_IMM2_31 1 "Deactive" 2 "Active" ;
VAL_ 2332107439 M2I_Byrack_ReVeEnable_IMM2_31 0 "invalid" 1 "Read SW-Version" 2 "Read HW-Version" 3 "Barcode" ;
VAL_ 2332107665 M2I_Byrack_Enable_IMM3_01 1 "Deactive" 2 "Active" ;
VAL_ 2332107665 M2I_Byrack_ReVeEnable_IMM3_01 0 "invalid" 1 "Read SW-Version" 2 "Read HW-Version" 3 "Barcode" ;
VAL_ 2332107666 M2I_Byrack_Enable_IMM3_02 1 "Deactive" 2 "Active" ;
VAL_ 2332107666 M2I_Byrack_ReVeEnable_IMM3_02 0 "invalid" 1 "Read SW-Version" 2 "Read HW-Version" 3 "Barcode" ;
VAL_ 2332107667 M2I_Byrack_Enable_IMM3_03 1 "Deactive" 2 "Active" ;
VAL_ 2332107667 M2I_Byrack_ReVeEnable_IMM3_03 0 "invalid" 1 "Read SW-Version" 2 "Read HW-Version" 3 "Barcode" ;
VAL_ 2332107668 M2I_Byrack_Enable_IMM3_04 1 "Deactive" 2 "Active" ;
VAL_ 2332107668 M2I_Byrack_ReVeEnable_IMM3_04 0 "invalid" 1 "Read SW-Version" 2 "Read HW-Version" 3 "Barcode" ;
VAL_ 2332107669 M2I_Byrack_Enable_IMM3_05 1 "Deactive" 2 "Active" ;
VAL_ 2332107669 M2I_Byrack_ReVeEnable_IMM3_05 0 "invalid" 1 "Read SW-Version" 2 "Read HW-Version" 3 "Barcode" ;
VAL_ 2332107670 M2I_Byrack_Enable_IMM3_06 1 "Deactive" 2 "Active" ;
VAL_ 2332107670 M2I_Byrack_ReVeEnable_IMM3_06 0 "invalid" 1 "Read SW-Version" 2 "Read HW-Version" 3 "Barcode" ;
VAL_ 2332107671 M2I_Byrack_Enable_IMM3_07 1 "Deactive" 2 "Active" ;
VAL_ 2332107671 M2I_Byrack_ReVeEnable_IMM3_07 0 "invalid" 1 "Read SW-Version" 2 "Read HW-Version" 3 "Barcode" ;
VAL_ 2332107672 M2I_Byrack_Enable_IMM3_08 1 "Deactive" 2 "Active" ;
VAL_ 2332107672 M2I_Byrack_ReVeEnable_IMM3_08 0 "invalid" 1 "Read SW-Version" 2 "Read HW-Version" 3 "Barcode" ;
VAL_ 2332107673 M2I_Byrack_Enable_IMM3_09 1 "Deactive" 2 "Active" ;
VAL_ 2332107673 M2I_Byrack_ReVeEnable_IMM3_09 0 "invalid" 1 "Read SW-Version" 2 "Read HW-Version" 3 "Barcode" ;
VAL_ 2332107674 M2I_Byrack_Enable_IMM3_10 1 "Deactive" 2 "Active" ;
VAL_ 2332107674 M2I_Byrack_ReVeEnable_IMM3_10 0 "invalid" 1 "Read SW-Version" 2 "Read HW-Version" 3 "Barcode" ;
VAL_ 2332107675 M2I_Byrack_Enable_IMM3_11 1 "Deactive" 2 "Active" ;
VAL_ 2332107675 M2I_Byrack_ReVeEnable_IMM3_11 0 "invalid" 1 "Read SW-Version" 2 "Read HW-Version" 3 "Barcode" ;
VAL_ 2332107676 M2I_Byrack_Enable_IMM3_12 1 "Deactive" 2 "Active" ;
VAL_ 2332107676 M2I_Byrack_ReVeEnable_IMM3_12 0 "invalid" 1 "Read SW-Version" 2 "Read HW-Version" 3 "Barcode" ;
VAL_ 2332107677 M2I_Byrack_Enable_IMM3_13 1 "Deactive" 2 "Active" ;
VAL_ 2332107677 M2I_Byrack_ReVeEnable_IMM3_13 0 "invalid" 1 "Read SW-Version" 2 "Read HW-Version" 3 "Barcode" ;
VAL_ 2332107678 M2I_Byrack_Enable_IMM3_14 1 "Deactive" 2 "Active" ;
VAL_ 2332107678 M2I_Byrack_ReVeEnable_IMM3_14 0 "invalid" 1 "Read SW-Version" 2 "Read HW-Version" 3 "Barcode" ;
VAL_ 2332107679 M2I_Byrack_Enable_IMM3_15 1 "Deactive" 2 "Active" ;
VAL_ 2332107679 M2I_Byrack_ReVeEnable_IMM3_15 0 "invalid" 1 "Read SW-Version" 2 "Read HW-Version" 3 "Barcode" ;
VAL_ 2332107680 M2I_Byrack_Enable_IMM3_16 1 "Deactive" 2 "Active" ;
VAL_ 2332107680 M2I_Byrack_ReVeEnable_IMM3_16 0 "invalid" 1 "Read SW-Version" 2 "Read HW-Version" 3 "Barcode" ;
VAL_ 2332107681 M2I_Byrack_Enable_IMM3_17 1 "Deactive" 2 "Active" ;
VAL_ 2332107681 M2I_Byrack_ReVeEnable_IMM3_17 0 "invalid" 1 "Read SW-Version" 2 "Read HW-Version" 3 "Barcode" ;
VAL_ 2332107682 M2I_Byrack_Enable_IMM3_18 1 "Deactive" 2 "Active" ;
VAL_ 2332107682 M2I_Byrack_ReVeEnable_IMM3_18 0 "invalid" 1 "Read SW-Version" 2 "Read HW-Version" 3 "Barcode" ;
VAL_ 2332107683 M2I_Byrack_Enable_IMM3_19 1 "Deactive" 2 "Active" ;
VAL_ 2332107683 M2I_Byrack_ReVeEnable_IMM3_19 0 "invalid" 1 "Read SW-Version" 2 "Read HW-Version" 3 "Barcode" ;
VAL_ 2332107684 M2I_Byrack_Enable_IMM3_20 1 "Deactive" 2 "Active" ;
VAL_ 2332107684 M2I_Byrack_ReVeEnable_IMM3_20 0 "invalid" 1 "Read SW-Version" 2 "Read HW-Version" 3 "Barcode" ;
VAL_ 2332107685 M2I_Byrack_Enable_IMM3_21 1 "Deactive" 2 "Active" ;
VAL_ 2332107685 M2I_Byrack_ReVeEnable_IMM3_21 0 "invalid" 1 "Read SW-Version" 2 "Read HW-Version" 3 "Barcode" ;
VAL_ 2332107686 M2I_Byrack_Enable_IMM3_22 1 "Deactive" 2 "Active" ;
VAL_ 2332107686 M2I_Byrack_ReVeEnable_IMM3_22 0 "invalid" 1 "Read SW-Version" 2 "Read HW-Version" 3 "Barcode" ;
VAL_ 2332107687 M2I_Byrack_Enable_IMM3_23 1 "Deactive" 2 "Active" ;
VAL_ 2332107687 M2I_Byrack_ReVeEnable_IMM3_23 0 "invalid" 1 "Read SW-Version" 2 "Read HW-Version" 3 "Barcode" ;
VAL_ 2332107688 M2I_Byrack_Enable_IMM3_24 1 "Deactive" 2 "Active" ;
VAL_ 2332107688 M2I_Byrack_ReVeEnable_IMM3_24 0 "invalid" 1 "Read SW-Version" 2 "Read HW-Version" 3 "Barcode" ;
VAL_ 2332107689 M2I_Byrack_Enable_IMM3_25 1 "Deactive" 2 "Active" ;
VAL_ 2332107689 M2I_Byrack_ReVeEnable_IMM3_25 0 "invalid" 1 "Read SW-Version" 2 "Read HW-Version" 3 "Barcode" ;
VAL_ 2332107690 M2I_Byrack_Enable_IMM3_26 1 "Deactive" 2 "Active" ;
VAL_ 2332107690 M2I_Byrack_ReVeEnable_IMM3_26 0 "invalid" 1 "Read SW-Version" 2 "Read HW-Version" 3 "Barcode" ;
VAL_ 2332107691 M2I_Byrack_Enable_IMM3_27 1 "Deactive" 2 "Active" ;
VAL_ 2332107691 M2I_Byrack_ReVeEnable_IMM3_27 0 "invalid" 1 "Read SW-Version" 2 "Read HW-Version" 3 "Barcode" ;
VAL_ 2332107692 M2I_Byrack_Enable_IMM3_28 1 "Deactive" 2 "Active" ;
VAL_ 2332107692 M2I_Byrack_ReVeEnable_IMM3_28 0 "invalid" 1 "Read SW-Version" 2 "Read HW-Version" 3 "Barcode" ;
VAL_ 2332107693 M2I_Byrack_Enable_IMM3_29 1 "Deactive" 2 "Active" ;
VAL_ 2332107693 M2I_Byrack_ReVeEnable_IMM3_29 0 "invalid" 1 "Read SW-Version" 2 "Read HW-Version" 3 "Barcode" ;
VAL_ 2332107694 M2I_Byrack_Enable_IMM3_30 1 "Deactive" 2 "Active" ;
VAL_ 2332107694 M2I_Byrack_ReVeEnable_IMM3_30 0 "invalid" 1 "Read SW-Version" 2 "Read HW-Version" 3 "Barcode" ;
VAL_ 2332107695 M2I_Byrack_Enable_IMM3_31 1 "Deactive" 2 "Active" ;
VAL_ 2332107695 M2I_Byrack_ReVeEnable_IMM3_31 0 "invalid" 1 "Read SW-Version" 2 "Read HW-Version" 3 "Barcode" ;
VAL_ 2332107921 M2I_Byrack_Enable_IMM4_01 1 "Deactive" 2 "Active" ;
VAL_ 2332107921 M2I_Byrack_ReVeEnable_IMM4_01 0 "invalid" 1 "Read SW-Version" 2 "Read HW-Version" 3 "Barcode" ;
VAL_ 2332107922 M2I_Byrack_Enable_IMM4_02 1 "Deactive" 2 "Active" ;
VAL_ 2332107922 M2I_Byrack_ReVeEnable_IMM4_02 0 "invalid" 1 "Read SW-Version" 2 "Read HW-Version" 3 "Barcode" ;
VAL_ 2332107923 M2I_Byrack_Enable_IMM4_03 1 "Deactive" 2 "Active" ;
VAL_ 2332107923 M2I_Byrack_ReVeEnable_IMM4_03 0 "invalid" 1 "Read SW-Version" 2 "Read HW-Version" 3 "Barcode" ;
VAL_ 2332107924 M2I_Byrack_Enable_IMM4_04 1 "Deactive" 2 "Active" ;
VAL_ 2332107924 M2I_Byrack_ReVeEnable_IMM4_04 0 "invalid" 1 "Read SW-Version" 2 "Read HW-Version" 3 "Barcode" ;
VAL_ 2332107925 M2I_Byrack_Enable_IMM4_05 1 "Deactive" 2 "Active" ;
VAL_ 2332107925 M2I_Byrack_ReVeEnable_IMM4_05 0 "invalid" 1 "Read SW-Version" 2 "Read HW-Version" 3 "Barcode" ;
VAL_ 2332107926 M2I_Byrack_Enable_IMM4_06 1 "Deactive" 2 "Active" ;
VAL_ 2332107926 M2I_Byrack_ReVeEnable_IMM4_06 0 "invalid" 1 "Read SW-Version" 2 "Read HW-Version" 3 "Barcode" ;
VAL_ 2332107927 M2I_Byrack_Enable_IMM4_07 1 "Deactive" 2 "Active" ;
VAL_ 2332107927 M2I_Byrack_ReVeEnable_IMM4_07 0 "invalid" 1 "Read SW-Version" 2 "Read HW-Version" 3 "Barcode" ;
VAL_ 2332107928 M2I_Byrack_Enable_IMM4_08 1 "Deactive" 2 "Active" ;
VAL_ 2332107928 M2I_Byrack_ReVeEnable_IMM4_08 0 "invalid" 1 "Read SW-Version" 2 "Read HW-Version" 3 "Barcode" ;
VAL_ 2332107929 M2I_Byrack_Enable_IMM4_09 1 "Deactive" 2 "Active" ;
VAL_ 2332107929 M2I_Byrack_ReVeEnable_IMM4_09 0 "invalid" 1 "Read SW-Version" 2 "Read HW-Version" 3 "Barcode" ;
VAL_ 2332107930 M2I_Byrack_Enable_IMM4_10 1 "Deactive" 2 "Active" ;
VAL_ 2332107930 M2I_Byrack_ReVeEnable_IMM4_10 0 "invalid" 1 "Read SW-Version" 2 "Read HW-Version" 3 "Barcode" ;
VAL_ 2332107931 M2I_Byrack_Enable_IMM4_11 1 "Deactive" 2 "Active" ;
VAL_ 2332107931 M2I_Byrack_ReVeEnable_IMM4_11 0 "invalid" 1 "Read SW-Version" 2 "Read HW-Version" 3 "Barcode" ;
VAL_ 2332107932 M2I_Byrack_Enable_IMM4_12 1 "Deactive" 2 "Active" ;
VAL_ 2332107932 M2I_Byrack_ReVeEnable_IMM4_12 0 "invalid" 1 "Read SW-Version" 2 "Read HW-Version" 3 "Barcode" ;
VAL_ 2332107933 M2I_Byrack_Enable_IMM4_13 1 "Deactive" 2 "Active" ;
VAL_ 2332107933 M2I_Byrack_ReVeEnable_IMM4_13 0 "invalid" 1 "Read SW-Version" 2 "Read HW-Version" 3 "Barcode" ;
VAL_ 2332107934 M2I_Byrack_Enable_IMM4_14 1 "Deactive" 2 "Active" ;
VAL_ 2332107934 M2I_Byrack_ReVeEnable_IMM4_14 0 "invalid" 1 "Read SW-Version" 2 "Read HW-Version" 3 "Barcode" ;
VAL_ 2332107935 M2I_Byrack_Enable_IMM4_15 1 "Deactive" 2 "Active" ;
VAL_ 2332107935 M2I_Byrack_ReVeEnable_IMM4_15 0 "invalid" 1 "Read SW-Version" 2 "Read HW-Version" 3 "Barcode" ;
VAL_ 2332107936 M2I_Byrack_Enable_IMM4_16 1 "Deactive" 2 "Active" ;
VAL_ 2332107936 M2I_Byrack_ReVeEnable_IMM4_16 0 "invalid" 1 "Read SW-Version" 2 "Read HW-Version" 3 "Barcode" ;
VAL_ 2332107937 M2I_Byrack_Enable_IMM4_17 1 "Deactive" 2 "Active" ;
VAL_ 2332107937 M2I_Byrack_ReVeEnable_IMM4_17 0 "invalid" 1 "Read SW-Version" 2 "Read HW-Version" 3 "Barcode" ;
VAL_ 2332107938 M2I_Byrack_Enable_IMM4_18 1 "Deactive" 2 "Active" ;
VAL_ 2332107938 M2I_Byrack_ReVeEnable_IMM4_18 0 "invalid" 1 "Read SW-Version" 2 "Read HW-Version" 3 "Barcode" ;
VAL_ 2332107939 M2I_Byrack_Enable_IMM4_19 1 "Deactive" 2 "Active" ;
VAL_ 2332107939 M2I_Byrack_ReVeEnable_IMM4_19 0 "invalid" 1 "Read SW-Version" 2 "Read HW-Version" 3 "Barcode" ;
VAL_ 2332107940 M2I_Byrack_Enable_IMM4_20 1 "Deactive" 2 "Active" ;
VAL_ 2332107940 M2I_Byrack_ReVeEnable_IMM4_20 0 "invalid" 1 "Read SW-Version" 2 "Read HW-Version" 3 "Barcode" ;
VAL_ 2332107941 M2I_Byrack_Enable_IMM4_21 1 "Deactive" 2 "Active" ;
VAL_ 2332107941 M2I_Byrack_ReVeEnable_IMM4_21 0 "invalid" 1 "Read SW-Version" 2 "Read HW-Version" 3 "Barcode" ;
VAL_ 2332107942 M2I_Byrack_Enable_IMM4_22 1 "Deactive" 2 "Active" ;
VAL_ 2332107942 M2I_Byrack_ReVeEnable_IMM4_22 0 "invalid" 1 "Read SW-Version" 2 "Read HW-Version" 3 "Barcode" ;
VAL_ 2332107943 M2I_Byrack_Enable_IMM4_23 1 "Deactive" 2 "Active" ;
VAL_ 2332107943 M2I_Byrack_ReVeEnable_IMM4_23 0 "invalid" 1 "Read SW-Version" 2 "Read HW-Version" 3 "Barcode" ;
VAL_ 2332107944 M2I_Byrack_Enable_IMM4_24 1 "Deactive" 2 "Active" ;
VAL_ 2332107944 M2I_Byrack_ReVeEnable_IMM4_24 0 "invalid" 1 "Read SW-Version" 2 "Read HW-Version" 3 "Barcode" ;
VAL_ 2332107945 M2I_Byrack_Enable_IMM4_25 1 "Deactive" 2 "Active" ;
VAL_ 2332107945 M2I_Byrack_ReVeEnable_IMM4_25 0 "invalid" 1 "Read SW-Version" 2 "Read HW-Version" 3 "Barcode" ;
VAL_ 2332107946 M2I_Byrack_Enable_IMM4_26 1 "Deactive" 2 "Active" ;
VAL_ 2332107946 M2I_Byrack_ReVeEnable_IMM4_26 0 "invalid" 1 "Read SW-Version" 2 "Read HW-Version" 3 "Barcode" ;
VAL_ 2332107947 M2I_Byrack_Enable_IMM4_27 1 "Deactive" 2 "Active" ;
VAL_ 2332107947 M2I_Byrack_ReVeEnable_IMM4_27 0 "invalid" 1 "Read SW-Version" 2 "Read HW-Version" 3 "Barcode" ;
VAL_ 2332107948 M2I_Byrack_Enable_IMM4_28 1 "Deactive" 2 "Active" ;
VAL_ 2332107948 M2I_Byrack_ReVeEnable_IMM4_28 0 "invalid" 1 "Read SW-Version" 2 "Read HW-Version" 3 "Barcode" ;
VAL_ 2332107949 M2I_Byrack_Enable_IMM4_29 1 "Deactive" 2 "Active" ;
VAL_ 2332107949 M2I_Byrack_ReVeEnable_IMM4_29 0 "invalid" 1 "Read SW-Version" 2 "Read HW-Version" 3 "Barcode" ;
VAL_ 2332107950 M2I_Byrack_Enable_IMM4_30 1 "Deactive" 2 "Active" ;
VAL_ 2332107950 M2I_Byrack_ReVeEnable_IMM4_30 0 "invalid" 1 "Read SW-Version" 2 "Read HW-Version" 3 "Barcode" ;
VAL_ 2332107951 M2I_Byrack_Enable_IMM4_31 1 "Deactive" 2 "Active" ;
VAL_ 2332107951 M2I_Byrack_ReVeEnable_IMM4_31 0 "invalid" 1 "Read SW-Version" 2 "Read HW-Version" 3 "Barcode" ;
VAL_ 2332108177 M2I_Byrack_Enable_IMM5_01 1 "Deactive" 2 "Active" ;
VAL_ 2332108177 M2I_Byrack_ReVeEnable_IMM5_01 0 "invalid" 1 "Read SW-Version" 2 "Read HW-Version" 3 "Barcode" ;
VAL_ 2332108178 M2I_Byrack_Enable_IMM5_02 1 "Deactive" 2 "Active" ;
VAL_ 2332108178 M2I_Byrack_ReVeEnable_IMM5_02 0 "invalid" 1 "Read SW-Version" 2 "Read HW-Version" 3 "Barcode" ;
VAL_ 2332108179 M2I_Byrack_Enable_IMM5_03 1 "Deactive" 2 "Active" ;
VAL_ 2332108179 M2I_Byrack_ReVeEnable_IMM5_03 0 "invalid" 1 "Read SW-Version" 2 "Read HW-Version" 3 "Barcode" ;
VAL_ 2332108180 M2I_Byrack_Enable_IMM5_04 1 "Deactive" 2 "Active" ;
VAL_ 2332108180 M2I_Byrack_ReVeEnable_IMM5_04 0 "invalid" 1 "Read SW-Version" 2 "Read HW-Version" 3 "Barcode" ;
VAL_ 2332108181 M2I_Byrack_Enable_IMM5_05 1 "Deactive" 2 "Active" ;
VAL_ 2332108181 M2I_Byrack_ReVeEnable_IMM5_05 0 "invalid" 1 "Read SW-Version" 2 "Read HW-Version" 3 "Barcode" ;
VAL_ 2332108182 M2I_Byrack_Enable_IMM5_06 1 "Deactive" 2 "Active" ;
VAL_ 2332108182 M2I_Byrack_ReVeEnable_IMM5_06 0 "invalid" 1 "Read SW-Version" 2 "Read HW-Version" 3 "Barcode" ;
VAL_ 2332108183 M2I_Byrack_Enable_IMM5_07 1 "Deactive" 2 "Active" ;
VAL_ 2332108183 M2I_Byrack_ReVeEnable_IMM5_07 0 "invalid" 1 "Read SW-Version" 2 "Read HW-Version" 3 "Barcode" ;
VAL_ 2332108184 M2I_Byrack_Enable_IMM5_08 1 "Deactive" 2 "Active" ;
VAL_ 2332108184 M2I_Byrack_ReVeEnable_IMM5_08 0 "invalid" 1 "Read SW-Version" 2 "Read HW-Version" 3 "Barcode" ;
VAL_ 2332108185 M2I_Byrack_Enable_IMM5_09 1 "Deactive" 2 "Active" ;
VAL_ 2332108185 M2I_Byrack_ReVeEnable_IMM5_09 0 "invalid" 1 "Read SW-Version" 2 "Read HW-Version" 3 "Barcode" ;
VAL_ 2332108186 M2I_Byrack_Enable_IMM5_10 1 "Deactive" 2 "Active" ;
VAL_ 2332108186 M2I_Byrack_ReVeEnable_IMM5_10 0 "invalid" 1 "Read SW-Version" 2 "Read HW-Version" 3 "Barcode" ;
VAL_ 2332108187 M2I_Byrack_Enable_IMM5_11 1 "Deactive" 2 "Active" ;
VAL_ 2332108187 M2I_Byrack_ReVeEnable_IMM5_11 0 "invalid" 1 "Read SW-Version" 2 "Read HW-Version" 3 "Barcode" ;
VAL_ 2332108188 M2I_Byrack_Enable_IMM5_12 1 "Deactive" 2 "Active" ;
VAL_ 2332108188 M2I_Byrack_ReVeEnable_IMM5_12 0 "invalid" 1 "Read SW-Version" 2 "Read HW-Version" 3 "Barcode" ;
VAL_ 2332108189 M2I_Byrack_Enable_IMM5_13 1 "Deactive" 2 "Active" ;
VAL_ 2332108189 M2I_Byrack_ReVeEnable_IMM5_13 0 "invalid" 1 "Read SW-Version" 2 "Read HW-Version" 3 "Barcode" ;
VAL_ 2332108190 M2I_Byrack_Enable_IMM5_14 1 "Deactive" 2 "Active" ;
VAL_ 2332108190 M2I_Byrack_ReVeEnable_IMM5_14 0 "invalid" 1 "Read SW-Version" 2 "Read HW-Version" 3 "Barcode" ;
VERSION ""

NS_ :

BS_:

BU_: MBMU PC SBMU IMM ETH DCDC LEMS

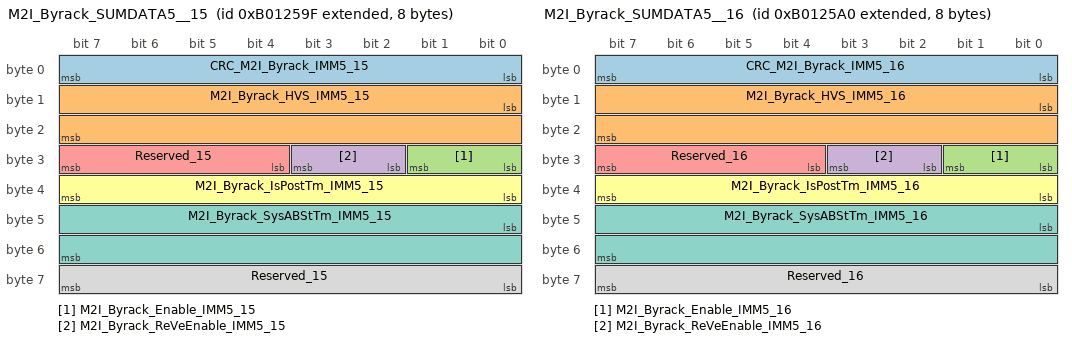
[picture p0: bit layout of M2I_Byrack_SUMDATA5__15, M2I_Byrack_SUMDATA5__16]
BO_ 2332108191 M2I_Byrack_SUMDATA5__15: 8 MBMU
 SG_ CRC_M2I_Byrack_IMM5_15 : 0|8@1+ (1,0) [0|255] ""  IMM
 SG_ M2I_Byrack_HVS_IMM5_15 : 8|16@1+ (0.1,0) [0|6553.5] "v"  IMM
 SG_ M2I_Byrack_Enable_IMM5_15 : 24|2@1+ (1,0) [0|3] ""  IMM
 SG_ M2I_Byrack_ReVeEnable_IMM5_15 : 26|2@1+ (1,0) [0|3] ""  IMM
 SG_ Reserved_15 : 28|4@1+ (1,0) [0|15] ""  IMM
 SG_ M2I_Byrack_IsPostTm_IMM5_15 : 32|8@1+ (0.01,0) [0|2.55] "s"  IMM
 SG_ M2I_Byrack_SysABStTm_IMM5_15 : 40|16@1+ (0.01,0) [0|655.35] "s"  IMM
 SG_ Reserved_15 : 56|8@1+ (1,0) [0|255] ""  IMM

BO_ 2332108192 M2I_Byrack_SUMDATA5__16: 8 MBMU
 SG_ CRC_M2I_Byrack_IMM5_16 : 0|8@1+ (1,0) [0|255] ""  IMM
 SG_ M2I_Byrack_HVS_IMM5_16 : 8|16@1+ (0.1,0) [0|6553.5] "v"  IMM
 SG_ M2I_Byrack_Enable_IMM5_16 : 24|2@1+ (1,0) [0|3] ""  IMM
 SG_ M2I_Byrack_ReVeEnable_IMM5_16 : 26|2@1+ (1,0) [0|3] ""  IMM
 SG_ Reserved_16 : 28|4@1+ (1,0) [0|15] ""  IMM
 SG_ M2I_Byrack_IsPostTm_IMM5_16 : 32|8@1+ (0.01,0) [0|2.55] "s"  IMM
 SG_ M2I_Byrack_SysABStTm_IMM5_16 : 40|16@1+ (0.01,0) [0|655.35] "s"  IMM
 SG_ Reserved_16 : 56|8@1+ (1,0) [0|255] ""  IMM

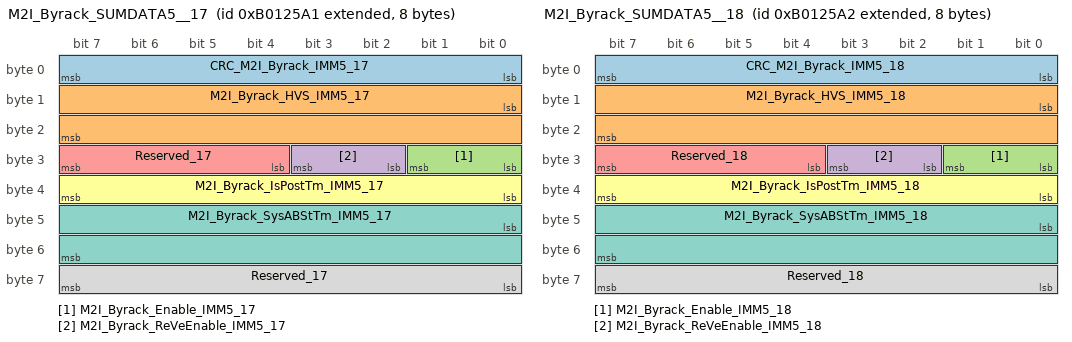
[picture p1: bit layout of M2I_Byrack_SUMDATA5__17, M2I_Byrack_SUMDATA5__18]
BO_ 2332108193 M2I_Byrack_SUMDATA5__17: 8 MBMU
 SG_ CRC_M2I_Byrack_IMM5_17 : 0|8@1+ (1,0) [0|255] ""  IMM
 SG_ M2I_Byrack_HVS_IMM5_17 : 8|16@1+ (0.1,0) [0|6553.5] "v"  IMM
 SG_ M2I_Byrack_Enable_IMM5_17 : 24|2@1+ (1,0) [0|3] ""  IMM
 SG_ M2I_Byrack_ReVeEnable_IMM5_17 : 26|2@1+ (1,0) [0|3] ""  IMM
 SG_ Reserved_17 : 28|4@1+ (1,0) [0|15] ""  IMM
 SG_ M2I_Byrack_IsPostTm_IMM5_17 : 32|8@1+ (0.01,0) [0|2.55] "s"  IMM
 SG_ M2I_Byrack_SysABStTm_IMM5_17 : 40|16@1+ (0.01,0) [0|655.35] "s"  IMM
 SG_ Reserved_17 : 56|8@1+ (1,0) [0|255] ""  IMM

BO_ 2332108194 M2I_Byrack_SUMDATA5__18: 8 MBMU
 SG_ CRC_M2I_Byrack_IMM5_18 : 0|8@1+ (1,0) [0|255] ""  IMM
 SG_ M2I_Byrack_HVS_IMM5_18 : 8|16@1+ (0.1,0) [0|6553.5] "v"  IMM
 SG_ M2I_Byrack_Enable_IMM5_18 : 24|2@1+ (1,0) [0|3] ""  IMM
 SG_ M2I_Byrack_ReVeEnable_IMM5_18 : 26|2@1+ (1,0) [0|3] ""  IMM
 SG_ Reserved_18 : 28|4@1+ (1,0) [0|15] ""  IMM
 SG_ M2I_Byrack_IsPostTm_IMM5_18 : 32|8@1+ (0.01,0) [0|2.55] "s"  IMM
 SG_ M2I_Byrack_SysABStTm_IMM5_18 : 40|16@1+ (0.01,0) [0|655.35] "s"  IMM
 SG_ Reserved_18 : 56|8@1+ (1,0) [0|255] ""  IMM

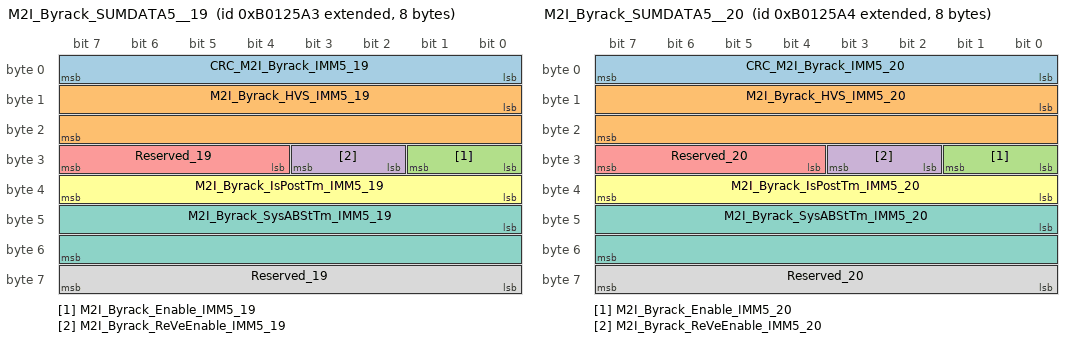
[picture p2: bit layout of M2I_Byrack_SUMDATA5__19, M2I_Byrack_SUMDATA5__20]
BO_ 2332108195 M2I_Byrack_SUMDATA5__19: 8 MBMU
 SG_ CRC_M2I_Byrack_IMM5_19 : 0|8@1+ (1,0) [0|255] ""  IMM
 SG_ M2I_Byrack_HVS_IMM5_19 : 8|16@1+ (0.1,0) [0|6553.5] "v"  IMM
 SG_ M2I_Byrack_Enable_IMM5_19 : 24|2@1+ (1,0) [0|3] ""  IMM
 SG_ M2I_Byrack_ReVeEnable_IMM5_19 : 26|2@1+ (1,0) [0|3] ""  IMM
 SG_ Reserved_19 : 28|4@1+ (1,0) [0|15] ""  IMM
 SG_ M2I_Byrack_IsPostTm_IMM5_19 : 32|8@1+ (0.01,0) [0|2.55] "s"  IMM
 SG_ M2I_Byrack_SysABStTm_IMM5_19 : 40|16@1+ (0.01,0) [0|655.35] "s"  IMM
 SG_ Reserved_19 : 56|8@1+ (1,0) [0|255] ""  IMM

BO_ 2332108196 M2I_Byrack_SUMDATA5__20: 8 MBMU
 SG_ CRC_M2I_Byrack_IMM5_20 : 0|8@1+ (1,0) [0|255] ""  IMM
 SG_ M2I_Byrack_HVS_IMM5_20 : 8|16@1+ (0.1,0) [0|6553.5] "v"  IMM
 SG_ M2I_Byrack_Enable_IMM5_20 : 24|2@1+ (1,0) [0|3] ""  IMM
 SG_ M2I_Byrack_ReVeEnable_IMM5_20 : 26|2@1+ (1,0) [0|3] ""  IMM
 SG_ Reserved_20 : 28|4@1+ (1,0) [0|15] ""  IMM
 SG_ M2I_Byrack_IsPostTm_IMM5_20 : 32|8@1+ (0.01,0) [0|2.55] "s"  IMM
 SG_ M2I_Byrack_SysABStTm_IMM5_20 : 40|16@1+ (0.01,0) [0|655.35] "s"  IMM
 SG_ Reserved_20 : 56|8@1+ (1,0) [0|255] ""  IMM

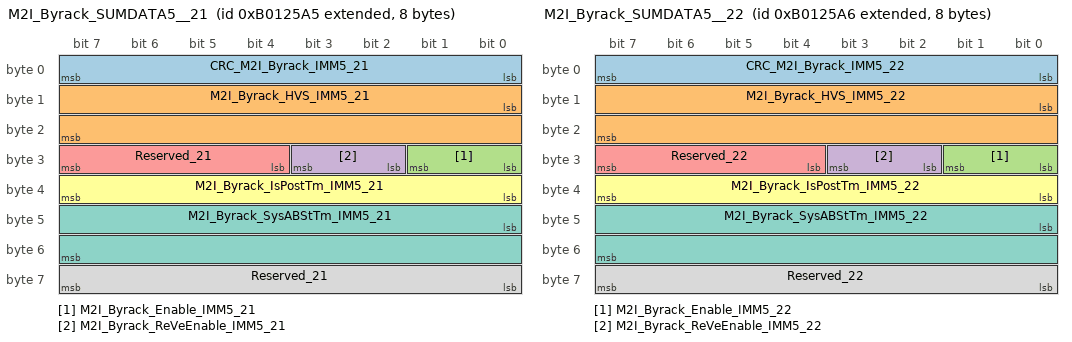
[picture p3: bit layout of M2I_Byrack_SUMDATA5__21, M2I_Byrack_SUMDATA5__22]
BO_ 2332108197 M2I_Byrack_SUMDATA5__21: 8 MBMU
 SG_ CRC_M2I_Byrack_IMM5_21 : 0|8@1+ (1,0) [0|255] ""  IMM
 SG_ M2I_Byrack_HVS_IMM5_21 : 8|16@1+ (0.1,0) [0|6553.5] "v"  IMM
 SG_ M2I_Byrack_Enable_IMM5_21 : 24|2@1+ (1,0) [0|3] ""  IMM
 SG_ M2I_Byrack_ReVeEnable_IMM5_21 : 26|2@1+ (1,0) [0|3] ""  IMM
 SG_ Reserved_21 : 28|4@1+ (1,0) [0|15] ""  IMM
 SG_ M2I_Byrack_IsPostTm_IMM5_21 : 32|8@1+ (0.01,0) [0|2.55] "s"  IMM
 SG_ M2I_Byrack_SysABStTm_IMM5_21 : 40|16@1+ (0.01,0) [0|655.35] "s"  IMM
 SG_ Reserved_21 : 56|8@1+ (1,0) [0|255] ""  IMM

BO_ 2332108198 M2I_Byrack_SUMDATA5__22: 8 MBMU
 SG_ CRC_M2I_Byrack_IMM5_22 : 0|8@1+ (1,0) [0|255] ""  IMM
 SG_ M2I_Byrack_HVS_IMM5_22 : 8|16@1+ (0.1,0) [0|6553.5] "v"  IMM
 SG_ M2I_Byrack_Enable_IMM5_22 : 24|2@1+ (1,0) [0|3] ""  IMM
 SG_ M2I_Byrack_ReVeEnable_IMM5_22 : 26|2@1+ (1,0) [0|3] ""  IMM
 SG_ Reserved_22 : 28|4@1+ (1,0) [0|15] ""  IMM
 SG_ M2I_Byrack_IsPostTm_IMM5_22 : 32|8@1+ (0.01,0) [0|2.55] "s"  IMM
 SG_ M2I_Byrack_SysABStTm_IMM5_22 : 40|16@1+ (0.01,0) [0|655.35] "s"  IMM
 SG_ Reserved_22 : 56|8@1+ (1,0) [0|255] ""  IMM

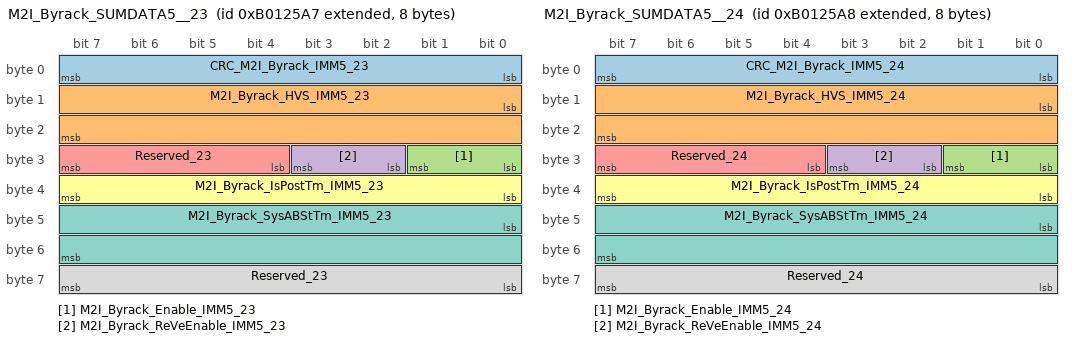
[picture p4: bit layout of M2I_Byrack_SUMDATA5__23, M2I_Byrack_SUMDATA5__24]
BO_ 2332108199 M2I_Byrack_SUMDATA5__23: 8 MBMU
 SG_ CRC_M2I_Byrack_IMM5_23 : 0|8@1+ (1,0) [0|255] ""  IMM
 SG_ M2I_Byrack_HVS_IMM5_23 : 8|16@1+ (0.1,0) [0|6553.5] "v"  IMM
 SG_ M2I_Byrack_Enable_IMM5_23 : 24|2@1+ (1,0) [0|3] ""  IMM
 SG_ M2I_Byrack_ReVeEnable_IMM5_23 : 26|2@1+ (1,0) [0|3] ""  IMM
 SG_ Reserved_23 : 28|4@1+ (1,0) [0|15] ""  IMM
 SG_ M2I_Byrack_IsPostTm_IMM5_23 : 32|8@1+ (0.01,0) [0|2.55] "s"  IMM
 SG_ M2I_Byrack_SysABStTm_IMM5_23 : 40|16@1+ (0.01,0) [0|655.35] "s"  IMM
 SG_ Reserved_23 : 56|8@1+ (1,0) [0|255] ""  IMM

BO_ 2332108200 M2I_Byrack_SUMDATA5__24: 8 MBMU
 SG_ CRC_M2I_Byrack_IMM5_24 : 0|8@1+ (1,0) [0|255] ""  IMM
 SG_ M2I_Byrack_HVS_IMM5_24 : 8|16@1+ (0.1,0) [0|6553.5] "v"  IMM
 SG_ M2I_Byrack_Enable_IMM5_24 : 24|2@1+ (1,0) [0|3] ""  IMM
 SG_ M2I_Byrack_ReVeEnable_IMM5_24 : 26|2@1+ (1,0) [0|3] ""  IMM
 SG_ Reserved_24 : 28|4@1+ (1,0) [0|15] ""  IMM
 SG_ M2I_Byrack_IsPostTm_IMM5_24 : 32|8@1+ (0.01,0) [0|2.55] "s"  IMM
 SG_ M2I_Byrack_SysABStTm_IMM5_24 : 40|16@1+ (0.01,0) [0|655.35] "s"  IMM
 SG_ Reserved_24 : 56|8@1+ (1,0) [0|255] ""  IMM

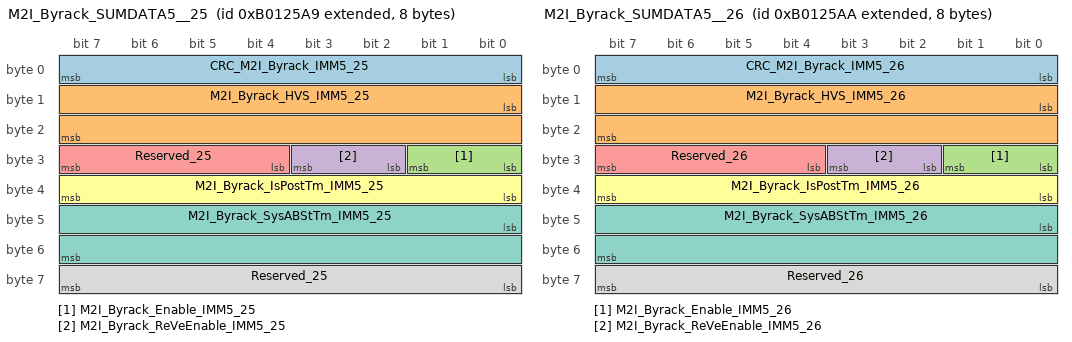
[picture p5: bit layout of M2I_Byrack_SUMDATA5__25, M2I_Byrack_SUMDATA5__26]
BO_ 2332108201 M2I_Byrack_SUMDATA5__25: 8 MBMU
 SG_ CRC_M2I_Byrack_IMM5_25 : 0|8@1+ (1,0) [0|255] ""  IMM
 SG_ M2I_Byrack_HVS_IMM5_25 : 8|16@1+ (0.1,0) [0|6553.5] "v"  IMM
 SG_ M2I_Byrack_Enable_IMM5_25 : 24|2@1+ (1,0) [0|3] ""  IMM
 SG_ M2I_Byrack_ReVeEnable_IMM5_25 : 26|2@1+ (1,0) [0|3] ""  IMM
 SG_ Reserved_25 : 28|4@1+ (1,0) [0|15] ""  IMM
 SG_ M2I_Byrack_IsPostTm_IMM5_25 : 32|8@1+ (0.01,0) [0|2.55] "s"  IMM
 SG_ M2I_Byrack_SysABStTm_IMM5_25 : 40|16@1+ (0.01,0) [0|655.35] "s"  IMM
 SG_ Reserved_25 : 56|8@1+ (1,0) [0|255] ""  IMM

BO_ 2332108202 M2I_Byrack_SUMDATA5__26: 8 MBMU
 SG_ CRC_M2I_Byrack_IMM5_26 : 0|8@1+ (1,0) [0|255] ""  IMM
 SG_ M2I_Byrack_HVS_IMM5_26 : 8|16@1+ (0.1,0) [0|6553.5] "v"  IMM
 SG_ M2I_Byrack_Enable_IMM5_26 : 24|2@1+ (1,0) [0|3] ""  IMM
 SG_ M2I_Byrack_ReVeEnable_IMM5_26 : 26|2@1+ (1,0) [0|3] ""  IMM
 SG_ Reserved_26 : 28|4@1+ (1,0) [0|15] ""  IMM
 SG_ M2I_Byrack_IsPostTm_IMM5_26 : 32|8@1+ (0.01,0) [0|2.55] "s"  IMM
 SG_ M2I_Byrack_SysABStTm_IMM5_26 : 40|16@1+ (0.01,0) [0|655.35] "s"  IMM
 SG_ Reserved_26 : 56|8@1+ (1,0) [0|255] ""  IMM

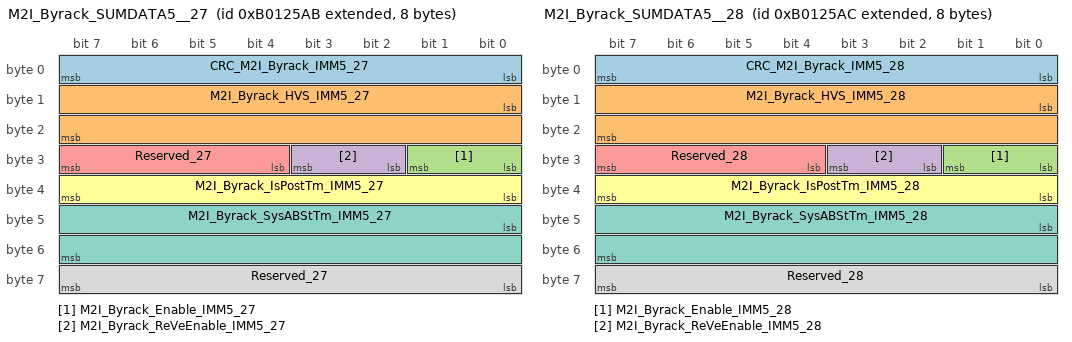
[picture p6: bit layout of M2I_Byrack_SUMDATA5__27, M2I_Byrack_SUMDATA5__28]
BO_ 2332108203 M2I_Byrack_SUMDATA5__27: 8 MBMU
 SG_ CRC_M2I_Byrack_IMM5_27 : 0|8@1+ (1,0) [0|255] ""  IMM
 SG_ M2I_Byrack_HVS_IMM5_27 : 8|16@1+ (0.1,0) [0|6553.5] "v"  IMM
 SG_ M2I_Byrack_Enable_IMM5_27 : 24|2@1+ (1,0) [0|3] ""  IMM
 SG_ M2I_Byrack_ReVeEnable_IMM5_27 : 26|2@1+ (1,0) [0|3] ""  IMM
 SG_ Reserved_27 : 28|4@1+ (1,0) [0|15] ""  IMM
 SG_ M2I_Byrack_IsPostTm_IMM5_27 : 32|8@1+ (0.01,0) [0|2.55] "s"  IMM
 SG_ M2I_Byrack_SysABStTm_IMM5_27 : 40|16@1+ (0.01,0) [0|655.35] "s"  IMM
 SG_ Reserved_27 : 56|8@1+ (1,0) [0|255] ""  IMM

BO_ 2332108204 M2I_Byrack_SUMDATA5__28: 8 MBMU
 SG_ CRC_M2I_Byrack_IMM5_28 : 0|8@1+ (1,0) [0|255] ""  IMM
 SG_ M2I_Byrack_HVS_IMM5_28 : 8|16@1+ (0.1,0) [0|6553.5] "v"  IMM
 SG_ M2I_Byrack_Enable_IMM5_28 : 24|2@1+ (1,0) [0|3] ""  IMM
 SG_ M2I_Byrack_ReVeEnable_IMM5_28 : 26|2@1+ (1,0) [0|3] ""  IMM
 SG_ Reserved_28 : 28|4@1+ (1,0) [0|15] ""  IMM
 SG_ M2I_Byrack_IsPostTm_IMM5_28 : 32|8@1+ (0.01,0) [0|2.55] "s"  IMM
 SG_ M2I_Byrack_SysABStTm_IMM5_28 : 40|16@1+ (0.01,0) [0|655.35] "s"  IMM
 SG_ Reserved_28 : 56|8@1+ (1,0) [0|255] ""  IMM

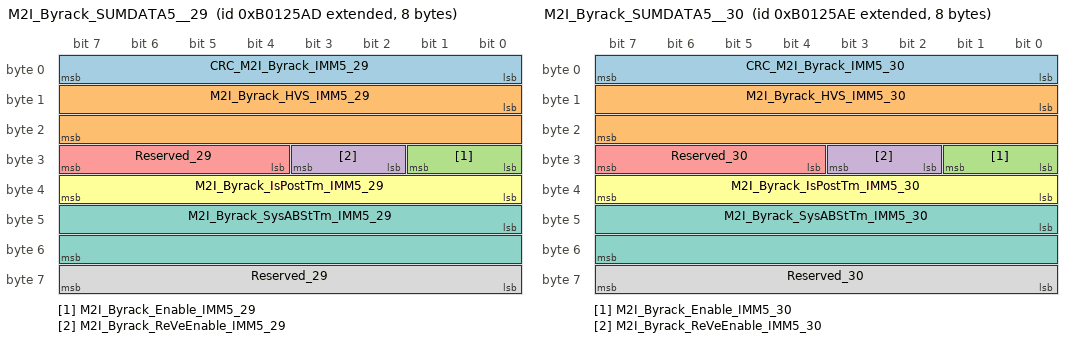
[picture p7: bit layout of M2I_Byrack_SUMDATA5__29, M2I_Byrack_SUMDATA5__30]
BO_ 2332108205 M2I_Byrack_SUMDATA5__29: 8 MBMU
 SG_ CRC_M2I_Byrack_IMM5_29 : 0|8@1+ (1,0) [0|255] ""  IMM
 SG_ M2I_Byrack_HVS_IMM5_29 : 8|16@1+ (0.1,0) [0|6553.5] "v"  IMM
 SG_ M2I_Byrack_Enable_IMM5_29 : 24|2@1+ (1,0) [0|3] ""  IMM
 SG_ M2I_Byrack_ReVeEnable_IMM5_29 : 26|2@1+ (1,0) [0|3] ""  IMM
 SG_ Reserved_29 : 28|4@1+ (1,0) [0|15] ""  IMM
 SG_ M2I_Byrack_IsPostTm_IMM5_29 : 32|8@1+ (0.01,0) [0|2.55] "s"  IMM
 SG_ M2I_Byrack_SysABStTm_IMM5_29 : 40|16@1+ (0.01,0) [0|655.35] "s"  IMM
 SG_ Reserved_29 : 56|8@1+ (1,0) [0|255] ""  IMM

BO_ 2332108206 M2I_Byrack_SUMDATA5__30: 8 MBMU
 SG_ CRC_M2I_Byrack_IMM5_30 : 0|8@1+ (1,0) [0|255] ""  IMM
 SG_ M2I_Byrack_HVS_IMM5_30 : 8|16@1+ (0.1,0) [0|6553.5] "v"  IMM
 SG_ M2I_Byrack_Enable_IMM5_30 : 24|2@1+ (1,0) [0|3] ""  IMM
 SG_ M2I_Byrack_ReVeEnable_IMM5_30 : 26|2@1+ (1,0) [0|3] ""  IMM
 SG_ Reserved_30 : 28|4@1+ (1,0) [0|15] ""  IMM
 SG_ M2I_Byrack_IsPostTm_IMM5_30 : 32|8@1+ (0.01,0) [0|2.55] "s"  IMM
 SG_ M2I_Byrack_SysABStTm_IMM5_30 : 40|16@1+ (0.01,0) [0|655.35] "s"  IMM
 SG_ Reserved_30 : 56|8@1+ (1,0) [0|255] ""  IMM

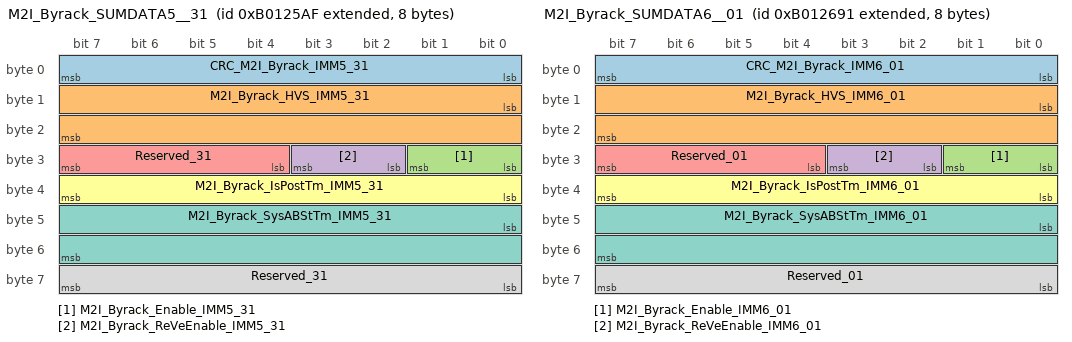
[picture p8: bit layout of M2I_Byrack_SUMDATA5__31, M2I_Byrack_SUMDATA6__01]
BO_ 2332108207 M2I_Byrack_SUMDATA5__31: 8 MBMU
 SG_ CRC_M2I_Byrack_IMM5_31 : 0|8@1+ (1,0) [0|255] ""  IMM
 SG_ M2I_Byrack_HVS_IMM5_31 : 8|16@1+ (0.1,0) [0|6553.5] "v"  IMM
 SG_ M2I_Byrack_Enable_IMM5_31 : 24|2@1+ (1,0) [0|3] ""  IMM
 SG_ M2I_Byrack_ReVeEnable_IMM5_31 : 26|2@1+ (1,0) [0|3] ""  IMM
 SG_ Reserved_31 : 28|4@1+ (1,0) [0|15] ""  IMM
 SG_ M2I_Byrack_IsPostTm_IMM5_31 : 32|8@1+ (0.01,0) [0|2.55] "s"  IMM
 SG_ M2I_Byrack_SysABStTm_IMM5_31 : 40|16@1+ (0.01,0) [0|655.35] "s"  IMM
 SG_ Reserved_31 : 56|8@1+ (1,0) [0|255] ""  IMM

BO_ 2332108433 M2I_Byrack_SUMDATA6__01: 8 MBMU
 SG_ CRC_M2I_Byrack_IMM6_01 : 0|8@1+ (1,0) [0|255] ""  IMM
 SG_ M2I_Byrack_HVS_IMM6_01 : 8|16@1+ (0.1,0) [0|6553.5] "v"  IMM
 SG_ M2I_Byrack_Enable_IMM6_01 : 24|2@1+ (1,0) [0|3] ""  IMM
 SG_ M2I_Byrack_ReVeEnable_IMM6_01 : 26|2@1+ (1,0) [0|3] ""  IMM
 SG_ Reserved_01 : 28|4@1+ (1,0) [0|15] ""  IMM
 SG_ M2I_Byrack_IsPostTm_IMM6_01 : 32|8@1+ (0.01,0) [0|2.55] "s"  IMM
 SG_ M2I_Byrack_SysABStTm_IMM6_01 : 40|16@1+ (0.01,0) [0|655.35] "s"  IMM
 SG_ Reserved_01 : 56|8@1+ (1,0) [0|255] ""  IMM

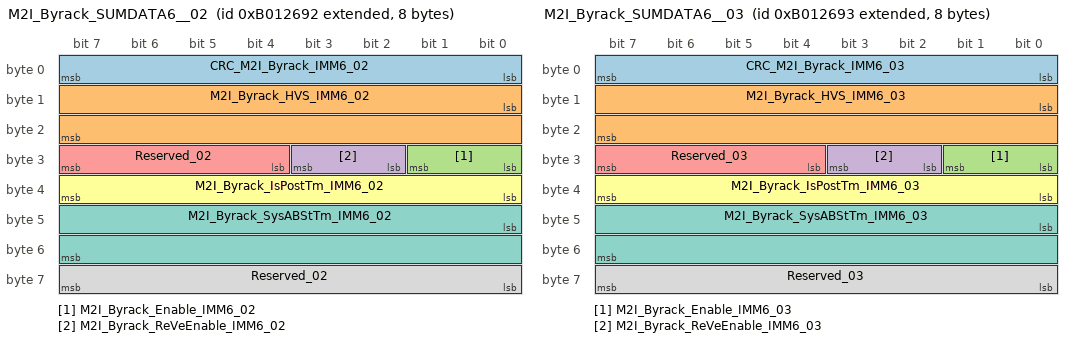
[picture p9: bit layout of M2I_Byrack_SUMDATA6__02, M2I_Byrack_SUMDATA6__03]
BO_ 2332108434 M2I_Byrack_SUMDATA6__02: 8 MBMU
 SG_ CRC_M2I_Byrack_IMM6_02 : 0|8@1+ (1,0) [0|255] ""  IMM
 SG_ M2I_Byrack_HVS_IMM6_02 : 8|16@1+ (0.1,0) [0|6553.5] "v"  IMM
 SG_ M2I_Byrack_Enable_IMM6_02 : 24|2@1+ (1,0) [0|3] ""  IMM
 SG_ M2I_Byrack_ReVeEnable_IMM6_02 : 26|2@1+ (1,0) [0|3] ""  IMM
 SG_ Reserved_02 : 28|4@1+ (1,0) [0|15] ""  IMM
 SG_ M2I_Byrack_IsPostTm_IMM6_02 : 32|8@1+ (0.01,0) [0|2.55] "s"  IMM
 SG_ M2I_Byrack_SysABStTm_IMM6_02 : 40|16@1+ (0.01,0) [0|655.35] "s"  IMM
 SG_ Reserved_02 : 56|8@1+ (1,0) [0|255] ""  IMM

BO_ 2332108435 M2I_Byrack_SUMDATA6__03: 8 MBMU
 SG_ CRC_M2I_Byrack_IMM6_03 : 0|8@1+ (1,0) [0|255] ""  IMM
 SG_ M2I_Byrack_HVS_IMM6_03 : 8|16@1+ (0.1,0) [0|6553.5] "v"  IMM
 SG_ M2I_Byrack_Enable_IMM6_03 : 24|2@1+ (1,0) [0|3] ""  IMM
 SG_ M2I_Byrack_ReVeEnable_IMM6_03 : 26|2@1+ (1,0) [0|3] ""  IMM
 SG_ Reserved_03 : 28|4@1+ (1,0) [0|15] ""  IMM
 SG_ M2I_Byrack_IsPostTm_IMM6_03 : 32|8@1+ (0.01,0) [0|2.55] "s"  IMM
 SG_ M2I_Byrack_SysABStTm_IMM6_03 : 40|16@1+ (0.01,0) [0|655.35] "s"  IMM
 SG_ Reserved_03 : 56|8@1+ (1,0) [0|255] ""  IMM

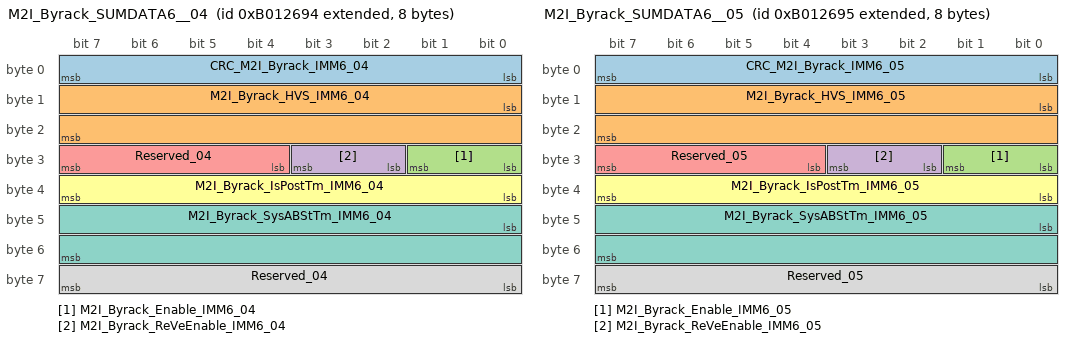
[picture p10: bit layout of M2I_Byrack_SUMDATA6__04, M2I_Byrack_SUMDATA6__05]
BO_ 2332108436 M2I_Byrack_SUMDATA6__04: 8 MBMU
 SG_ CRC_M2I_Byrack_IMM6_04 : 0|8@1+ (1,0) [0|255] ""  IMM
 SG_ M2I_Byrack_HVS_IMM6_04 : 8|16@1+ (0.1,0) [0|6553.5] "v"  IMM
 SG_ M2I_Byrack_Enable_IMM6_04 : 24|2@1+ (1,0) [0|3] ""  IMM
 SG_ M2I_Byrack_ReVeEnable_IMM6_04 : 26|2@1+ (1,0) [0|3] ""  IMM
 SG_ Reserved_04 : 28|4@1+ (1,0) [0|15] ""  IMM
 SG_ M2I_Byrack_IsPostTm_IMM6_04 : 32|8@1+ (0.01,0) [0|2.55] "s"  IMM
 SG_ M2I_Byrack_SysABStTm_IMM6_04 : 40|16@1+ (0.01,0) [0|655.35] "s"  IMM
 SG_ Reserved_04 : 56|8@1+ (1,0) [0|255] ""  IMM

BO_ 2332108437 M2I_Byrack_SUMDATA6__05: 8 MBMU
 SG_ CRC_M2I_Byrack_IMM6_05 : 0|8@1+ (1,0) [0|255] ""  IMM
 SG_ M2I_Byrack_HVS_IMM6_05 : 8|16@1+ (0.1,0) [0|6553.5] "v"  IMM
 SG_ M2I_Byrack_Enable_IMM6_05 : 24|2@1+ (1,0) [0|3] ""  IMM
 SG_ M2I_Byrack_ReVeEnable_IMM6_05 : 26|2@1+ (1,0) [0|3] ""  IMM
 SG_ Reserved_05 : 28|4@1+ (1,0) [0|15] ""  IMM
 SG_ M2I_Byrack_IsPostTm_IMM6_05 : 32|8@1+ (0.01,0) [0|2.55] "s"  IMM
 SG_ M2I_Byrack_SysABStTm_IMM6_05 : 40|16@1+ (0.01,0) [0|655.35] "s"  IMM
 SG_ Reserved_05 : 56|8@1+ (1,0) [0|255] ""  IMM

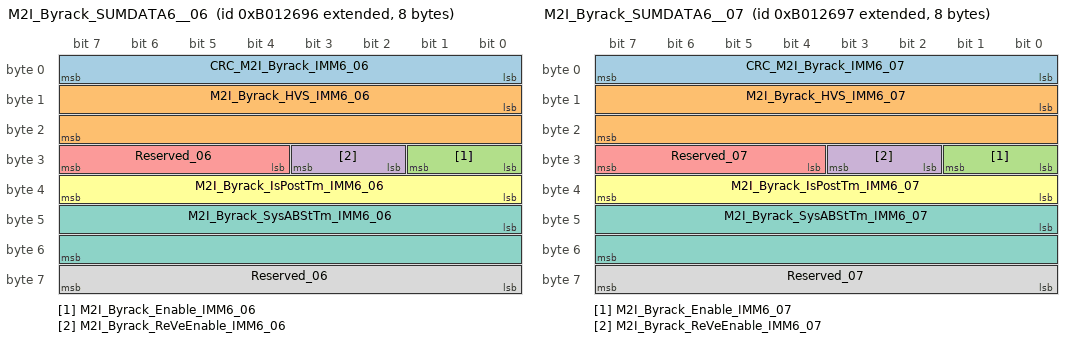
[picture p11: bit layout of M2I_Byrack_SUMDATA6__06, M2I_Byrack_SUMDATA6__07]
BO_ 2332108438 M2I_Byrack_SUMDATA6__06: 8 MBMU
 SG_ CRC_M2I_Byrack_IMM6_06 : 0|8@1+ (1,0) [0|255] ""  IMM
 SG_ M2I_Byrack_HVS_IMM6_06 : 8|16@1+ (0.1,0) [0|6553.5] "v"  IMM
 SG_ M2I_Byrack_Enable_IMM6_06 : 24|2@1+ (1,0) [0|3] ""  IMM
 SG_ M2I_Byrack_ReVeEnable_IMM6_06 : 26|2@1+ (1,0) [0|3] ""  IMM
 SG_ Reserved_06 : 28|4@1+ (1,0) [0|15] ""  IMM
 SG_ M2I_Byrack_IsPostTm_IMM6_06 : 32|8@1+ (0.01,0) [0|2.55] "s"  IMM
 SG_ M2I_Byrack_SysABStTm_IMM6_06 : 40|16@1+ (0.01,0) [0|655.35] "s"  IMM
 SG_ Reserved_06 : 56|8@1+ (1,0) [0|255] ""  IMM

BO_ 2332108439 M2I_Byrack_SUMDATA6__07: 8 MBMU
 SG_ CRC_M2I_Byrack_IMM6_07 : 0|8@1+ (1,0) [0|255] ""  IMM
 SG_ M2I_Byrack_HVS_IMM6_07 : 8|16@1+ (0.1,0) [0|6553.5] "v"  IMM
 SG_ M2I_Byrack_Enable_IMM6_07 : 24|2@1+ (1,0) [0|3] ""  IMM
 SG_ M2I_Byrack_ReVeEnable_IMM6_07 : 26|2@1+ (1,0) [0|3] ""  IMM
 SG_ Reserved_07 : 28|4@1+ (1,0) [0|15] ""  IMM
 SG_ M2I_Byrack_IsPostTm_IMM6_07 : 32|8@1+ (0.01,0) [0|2.55] "s"  IMM
 SG_ M2I_Byrack_SysABStTm_IMM6_07 : 40|16@1+ (0.01,0) [0|655.35] "s"  IMM
 SG_ Reserved_07 : 56|8@1+ (1,0) [0|255] ""  IMM

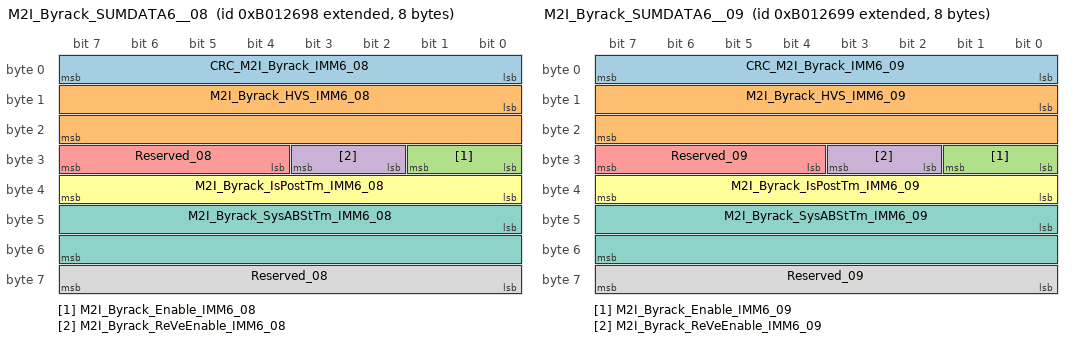
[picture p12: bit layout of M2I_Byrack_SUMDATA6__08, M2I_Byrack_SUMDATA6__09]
BO_ 2332108440 M2I_Byrack_SUMDATA6__08: 8 MBMU
 SG_ CRC_M2I_Byrack_IMM6_08 : 0|8@1+ (1,0) [0|255] ""  IMM
 SG_ M2I_Byrack_HVS_IMM6_08 : 8|16@1+ (0.1,0) [0|6553.5] "v"  IMM
 SG_ M2I_Byrack_Enable_IMM6_08 : 24|2@1+ (1,0) [0|3] ""  IMM
 SG_ M2I_Byrack_ReVeEnable_IMM6_08 : 26|2@1+ (1,0) [0|3] ""  IMM
 SG_ Reserved_08 : 28|4@1+ (1,0) [0|15] ""  IMM
 SG_ M2I_Byrack_IsPostTm_IMM6_08 : 32|8@1+ (0.01,0) [0|2.55] "s"  IMM
 SG_ M2I_Byrack_SysABStTm_IMM6_08 : 40|16@1+ (0.01,0) [0|655.35] "s"  IMM
 SG_ Reserved_08 : 56|8@1+ (1,0) [0|255] ""  IMM

BO_ 2332108441 M2I_Byrack_SUMDATA6__09: 8 MBMU
 SG_ CRC_M2I_Byrack_IMM6_09 : 0|8@1+ (1,0) [0|255] ""  IMM
 SG_ M2I_Byrack_HVS_IMM6_09 : 8|16@1+ (0.1,0) [0|6553.5] "v"  IMM
 SG_ M2I_Byrack_Enable_IMM6_09 : 24|2@1+ (1,0) [0|3] ""  IMM
 SG_ M2I_Byrack_ReVeEnable_IMM6_09 : 26|2@1+ (1,0) [0|3] ""  IMM
 SG_ Reserved_09 : 28|4@1+ (1,0) [0|15] ""  IMM
 SG_ M2I_Byrack_IsPostTm_IMM6_09 : 32|8@1+ (0.01,0) [0|2.55] "s"  IMM
 SG_ M2I_Byrack_SysABStTm_IMM6_09 : 40|16@1+ (0.01,0) [0|655.35] "s"  IMM
 SG_ Reserved_09 : 56|8@1+ (1,0) [0|255] ""  IMM

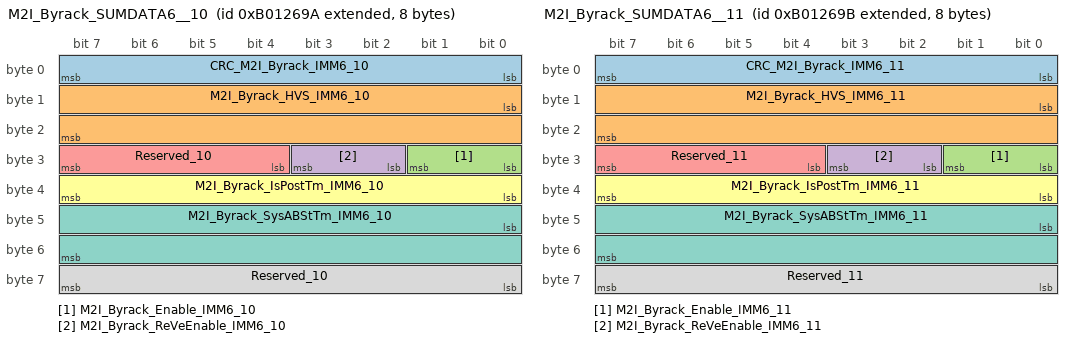
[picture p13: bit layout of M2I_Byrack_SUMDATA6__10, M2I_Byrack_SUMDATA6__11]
BO_ 2332108442 M2I_Byrack_SUMDATA6__10: 8 MBMU
 SG_ CRC_M2I_Byrack_IMM6_10 : 0|8@1+ (1,0) [0|255] ""  IMM
 SG_ M2I_Byrack_HVS_IMM6_10 : 8|16@1+ (0.1,0) [0|6553.5] "v"  IMM
 SG_ M2I_Byrack_Enable_IMM6_10 : 24|2@1+ (1,0) [0|3] ""  IMM
 SG_ M2I_Byrack_ReVeEnable_IMM6_10 : 26|2@1+ (1,0) [0|3] ""  IMM
 SG_ Reserved_10 : 28|4@1+ (1,0) [0|15] ""  IMM
 SG_ M2I_Byrack_IsPostTm_IMM6_10 : 32|8@1+ (0.01,0) [0|2.55] "s"  IMM
 SG_ M2I_Byrack_SysABStTm_IMM6_10 : 40|16@1+ (0.01,0) [0|655.35] "s"  IMM
 SG_ Reserved_10 : 56|8@1+ (1,0) [0|255] ""  IMM

BO_ 2332108443 M2I_Byrack_SUMDATA6__11: 8 MBMU
 SG_ CRC_M2I_Byrack_IMM6_11 : 0|8@1+ (1,0) [0|255] ""  IMM
 SG_ M2I_Byrack_HVS_IMM6_11 : 8|16@1+ (0.1,0) [0|6553.5] "v"  IMM
 SG_ M2I_Byrack_Enable_IMM6_11 : 24|2@1+ (1,0) [0|3] ""  IMM
 SG_ M2I_Byrack_ReVeEnable_IMM6_11 : 26|2@1+ (1,0) [0|3] ""  IMM
 SG_ Reserved_11 : 28|4@1+ (1,0) [0|15] ""  IMM
 SG_ M2I_Byrack_IsPostTm_IMM6_11 : 32|8@1+ (0.01,0) [0|2.55] "s"  IMM
 SG_ M2I_Byrack_SysABStTm_IMM6_11 : 40|16@1+ (0.01,0) [0|655.35] "s"  IMM
 SG_ Reserved_11 : 56|8@1+ (1,0) [0|255] ""  IMM

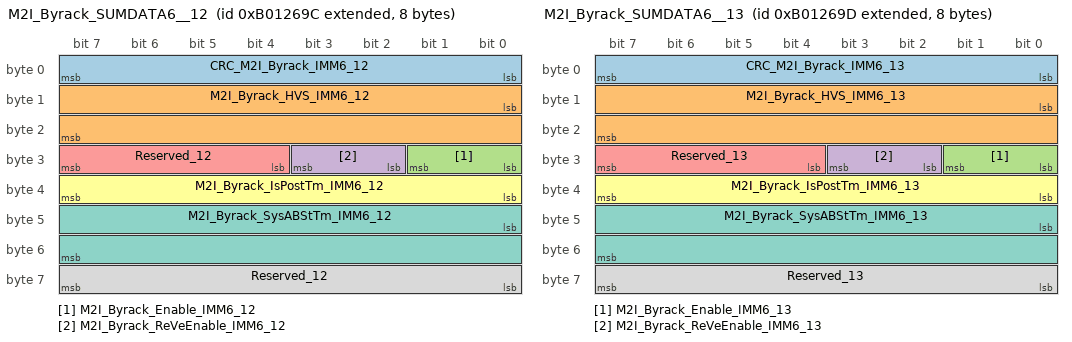
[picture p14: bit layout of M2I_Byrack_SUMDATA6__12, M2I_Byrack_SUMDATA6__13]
BO_ 2332108444 M2I_Byrack_SUMDATA6__12: 8 MBMU
 SG_ CRC_M2I_Byrack_IMM6_12 : 0|8@1+ (1,0) [0|255] ""  IMM
 SG_ M2I_Byrack_HVS_IMM6_12 : 8|16@1+ (0.1,0) [0|6553.5] "v"  IMM
 SG_ M2I_Byrack_Enable_IMM6_12 : 24|2@1+ (1,0) [0|3] ""  IMM
 SG_ M2I_Byrack_ReVeEnable_IMM6_12 : 26|2@1+ (1,0) [0|3] ""  IMM
 SG_ Reserved_12 : 28|4@1+ (1,0) [0|15] ""  IMM
 SG_ M2I_Byrack_IsPostTm_IMM6_12 : 32|8@1+ (0.01,0) [0|2.55] "s"  IMM
 SG_ M2I_Byrack_SysABStTm_IMM6_12 : 40|16@1+ (0.01,0) [0|655.35] "s"  IMM
 SG_ Reserved_12 : 56|8@1+ (1,0) [0|255] ""  IMM

BO_ 2332108445 M2I_Byrack_SUMDATA6__13: 8 MBMU
 SG_ CRC_M2I_Byrack_IMM6_13 : 0|8@1+ (1,0) [0|255] ""  IMM
 SG_ M2I_Byrack_HVS_IMM6_13 : 8|16@1+ (0.1,0) [0|6553.5] "v"  IMM
 SG_ M2I_Byrack_Enable_IMM6_13 : 24|2@1+ (1,0) [0|3] ""  IMM
 SG_ M2I_Byrack_ReVeEnable_IMM6_13 : 26|2@1+ (1,0) [0|3] ""  IMM
 SG_ Reserved_13 : 28|4@1+ (1,0) [0|15] ""  IMM
 SG_ M2I_Byrack_IsPostTm_IMM6_13 : 32|8@1+ (0.01,0) [0|2.55] "s"  IMM
 SG_ M2I_Byrack_SysABStTm_IMM6_13 : 40|16@1+ (0.01,0) [0|655.35] "s"  IMM
 SG_ Reserved_13 : 56|8@1+ (1,0) [0|255] ""  IMM

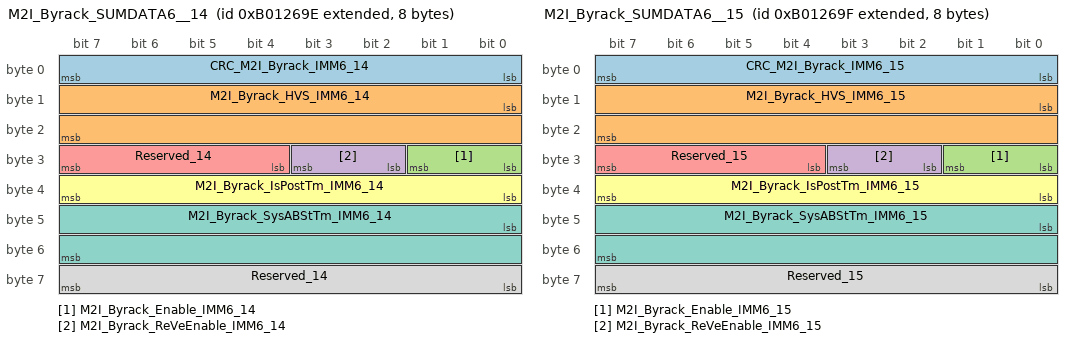
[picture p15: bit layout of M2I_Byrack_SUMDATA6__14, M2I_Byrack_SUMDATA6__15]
BO_ 2332108446 M2I_Byrack_SUMDATA6__14: 8 MBMU
 SG_ CRC_M2I_Byrack_IMM6_14 : 0|8@1+ (1,0) [0|255] ""  IMM
 SG_ M2I_Byrack_HVS_IMM6_14 : 8|16@1+ (0.1,0) [0|6553.5] "v"  IMM
 SG_ M2I_Byrack_Enable_IMM6_14 : 24|2@1+ (1,0) [0|3] ""  IMM
 SG_ M2I_Byrack_ReVeEnable_IMM6_14 : 26|2@1+ (1,0) [0|3] ""  IMM
 SG_ Reserved_14 : 28|4@1+ (1,0) [0|15] ""  IMM
 SG_ M2I_Byrack_IsPostTm_IMM6_14 : 32|8@1+ (0.01,0) [0|2.55] "s"  IMM
 SG_ M2I_Byrack_SysABStTm_IMM6_14 : 40|16@1+ (0.01,0) [0|655.35] "s"  IMM
 SG_ Reserved_14 : 56|8@1+ (1,0) [0|255] ""  IMM

BO_ 2332108447 M2I_Byrack_SUMDATA6__15: 8 MBMU
 SG_ CRC_M2I_Byrack_IMM6_15 : 0|8@1+ (1,0) [0|255] ""  IMM
 SG_ M2I_Byrack_HVS_IMM6_15 : 8|16@1+ (0.1,0) [0|6553.5] "v"  IMM
 SG_ M2I_Byrack_Enable_IMM6_15 : 24|2@1+ (1,0) [0|3] ""  IMM
 SG_ M2I_Byrack_ReVeEnable_IMM6_15 : 26|2@1+ (1,0) [0|3] ""  IMM
 SG_ Reserved_15 : 28|4@1+ (1,0) [0|15] ""  IMM
 SG_ M2I_Byrack_IsPostTm_IMM6_15 : 32|8@1+ (0.01,0) [0|2.55] "s"  IMM
 SG_ M2I_Byrack_SysABStTm_IMM6_15 : 40|16@1+ (0.01,0) [0|655.35] "s"  IMM
 SG_ Reserved_15 : 56|8@1+ (1,0) [0|255] ""  IMM

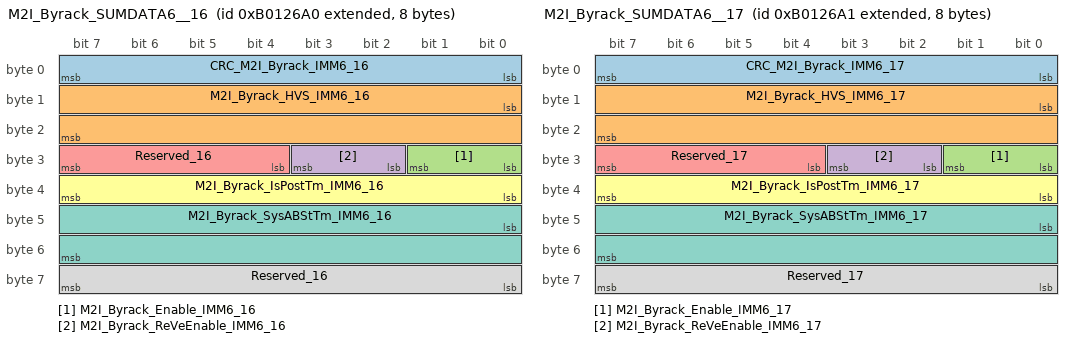
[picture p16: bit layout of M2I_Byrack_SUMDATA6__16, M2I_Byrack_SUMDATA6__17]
BO_ 2332108448 M2I_Byrack_SUMDATA6__16: 8 MBMU
 SG_ CRC_M2I_Byrack_IMM6_16 : 0|8@1+ (1,0) [0|255] ""  IMM
 SG_ M2I_Byrack_HVS_IMM6_16 : 8|16@1+ (0.1,0) [0|6553.5] "v"  IMM
 SG_ M2I_Byrack_Enable_IMM6_16 : 24|2@1+ (1,0) [0|3] ""  IMM
 SG_ M2I_Byrack_ReVeEnable_IMM6_16 : 26|2@1+ (1,0) [0|3] ""  IMM
 SG_ Reserved_16 : 28|4@1+ (1,0) [0|15] ""  IMM
 SG_ M2I_Byrack_IsPostTm_IMM6_16 : 32|8@1+ (0.01,0) [0|2.55] "s"  IMM
 SG_ M2I_Byrack_SysABStTm_IMM6_16 : 40|16@1+ (0.01,0) [0|655.35] "s"  IMM
 SG_ Reserved_16 : 56|8@1+ (1,0) [0|255] ""  IMM

BO_ 2332108449 M2I_Byrack_SUMDATA6__17: 8 MBMU
 SG_ CRC_M2I_Byrack_IMM6_17 : 0|8@1+ (1,0) [0|255] ""  IMM
 SG_ M2I_Byrack_HVS_IMM6_17 : 8|16@1+ (0.1,0) [0|6553.5] "v"  IMM
 SG_ M2I_Byrack_Enable_IMM6_17 : 24|2@1+ (1,0) [0|3] ""  IMM
 SG_ M2I_Byrack_ReVeEnable_IMM6_17 : 26|2@1+ (1,0) [0|3] ""  IMM
 SG_ Reserved_17 : 28|4@1+ (1,0) [0|15] ""  IMM
 SG_ M2I_Byrack_IsPostTm_IMM6_17 : 32|8@1+ (0.01,0) [0|2.55] "s"  IMM
 SG_ M2I_Byrack_SysABStTm_IMM6_17 : 40|16@1+ (0.01,0) [0|655.35] "s"  IMM
 SG_ Reserved_17 : 56|8@1+ (1,0) [0|255] ""  IMM

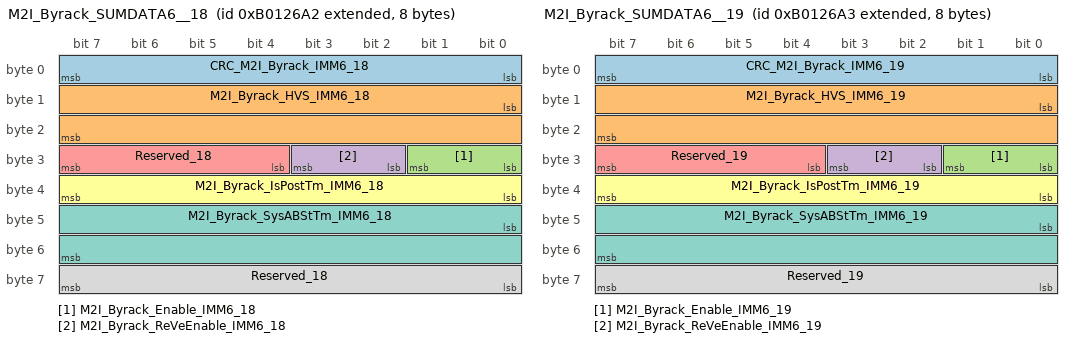
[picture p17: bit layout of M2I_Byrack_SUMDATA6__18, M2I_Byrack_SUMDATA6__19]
BO_ 2332108450 M2I_Byrack_SUMDATA6__18: 8 MBMU
 SG_ CRC_M2I_Byrack_IMM6_18 : 0|8@1+ (1,0) [0|255] ""  IMM
 SG_ M2I_Byrack_HVS_IMM6_18 : 8|16@1+ (0.1,0) [0|6553.5] "v"  IMM
 SG_ M2I_Byrack_Enable_IMM6_18 : 24|2@1+ (1,0) [0|3] ""  IMM
 SG_ M2I_Byrack_ReVeEnable_IMM6_18 : 26|2@1+ (1,0) [0|3] ""  IMM
 SG_ Reserved_18 : 28|4@1+ (1,0) [0|15] ""  IMM
 SG_ M2I_Byrack_IsPostTm_IMM6_18 : 32|8@1+ (0.01,0) [0|2.55] "s"  IMM
 SG_ M2I_Byrack_SysABStTm_IMM6_18 : 40|16@1+ (0.01,0) [0|655.35] "s"  IMM
 SG_ Reserved_18 : 56|8@1+ (1,0) [0|255] ""  IMM

BO_ 2332108451 M2I_Byrack_SUMDATA6__19: 8 MBMU
 SG_ CRC_M2I_Byrack_IMM6_19 : 0|8@1+ (1,0) [0|255] ""  IMM
 SG_ M2I_Byrack_HVS_IMM6_19 : 8|16@1+ (0.1,0) [0|6553.5] "v"  IMM
 SG_ M2I_Byrack_Enable_IMM6_19 : 24|2@1+ (1,0) [0|3] ""  IMM
 SG_ M2I_Byrack_ReVeEnable_IMM6_19 : 26|2@1+ (1,0) [0|3] ""  IMM
 SG_ Reserved_19 : 28|4@1+ (1,0) [0|15] ""  IMM
 SG_ M2I_Byrack_IsPostTm_IMM6_19 : 32|8@1+ (0.01,0) [0|2.55] "s"  IMM
 SG_ M2I_Byrack_SysABStTm_IMM6_19 : 40|16@1+ (0.01,0) [0|655.35] "s"  IMM
 SG_ Reserved_19 : 56|8@1+ (1,0) [0|255] ""  IMM

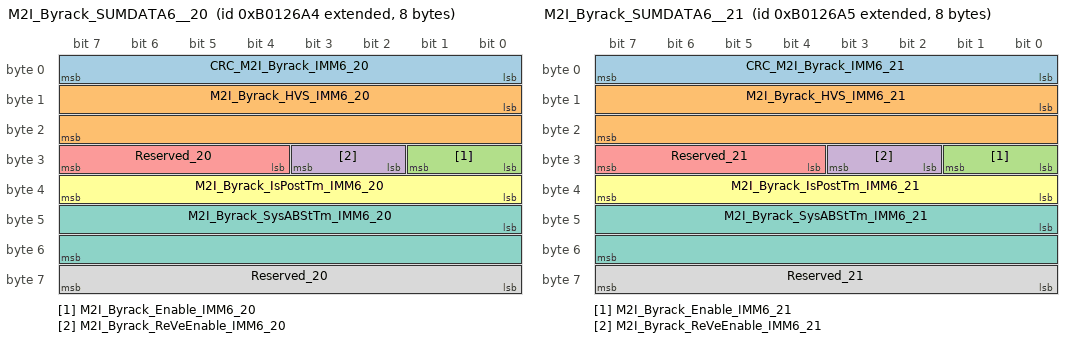
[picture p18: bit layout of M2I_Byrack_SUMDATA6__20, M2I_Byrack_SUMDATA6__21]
BO_ 2332108452 M2I_Byrack_SUMDATA6__20: 8 MBMU
 SG_ CRC_M2I_Byrack_IMM6_20 : 0|8@1+ (1,0) [0|255] ""  IMM
 SG_ M2I_Byrack_HVS_IMM6_20 : 8|16@1+ (0.1,0) [0|6553.5] "v"  IMM
 SG_ M2I_Byrack_Enable_IMM6_20 : 24|2@1+ (1,0) [0|3] ""  IMM
 SG_ M2I_Byrack_ReVeEnable_IMM6_20 : 26|2@1+ (1,0) [0|3] ""  IMM
 SG_ Reserved_20 : 28|4@1+ (1,0) [0|15] ""  IMM
 SG_ M2I_Byrack_IsPostTm_IMM6_20 : 32|8@1+ (0.01,0) [0|2.55] "s"  IMM
 SG_ M2I_Byrack_SysABStTm_IMM6_20 : 40|16@1+ (0.01,0) [0|655.35] "s"  IMM
 SG_ Reserved_20 : 56|8@1+ (1,0) [0|255] ""  IMM

BO_ 2332108453 M2I_Byrack_SUMDATA6__21: 8 MBMU
 SG_ CRC_M2I_Byrack_IMM6_21 : 0|8@1+ (1,0) [0|255] ""  IMM
 SG_ M2I_Byrack_HVS_IMM6_21 : 8|16@1+ (0.1,0) [0|6553.5] "v"  IMM
 SG_ M2I_Byrack_Enable_IMM6_21 : 24|2@1+ (1,0) [0|3] ""  IMM
 SG_ M2I_Byrack_ReVeEnable_IMM6_21 : 26|2@1+ (1,0) [0|3] ""  IMM
 SG_ Reserved_21 : 28|4@1+ (1,0) [0|15] ""  IMM
 SG_ M2I_Byrack_IsPostTm_IMM6_21 : 32|8@1+ (0.01,0) [0|2.55] "s"  IMM
 SG_ M2I_Byrack_SysABStTm_IMM6_21 : 40|16@1+ (0.01,0) [0|655.35] "s"  IMM
 SG_ Reserved_21 : 56|8@1+ (1,0) [0|255] ""  IMM

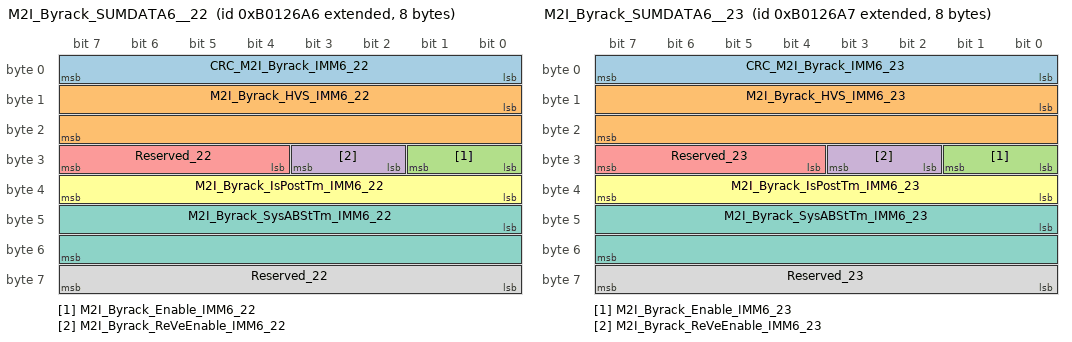
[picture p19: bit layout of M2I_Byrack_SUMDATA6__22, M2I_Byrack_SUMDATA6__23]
BO_ 2332108454 M2I_Byrack_SUMDATA6__22: 8 MBMU
 SG_ CRC_M2I_Byrack_IMM6_22 : 0|8@1+ (1,0) [0|255] ""  IMM
 SG_ M2I_Byrack_HVS_IMM6_22 : 8|16@1+ (0.1,0) [0|6553.5] "v"  IMM
 SG_ M2I_Byrack_Enable_IMM6_22 : 24|2@1+ (1,0) [0|3] ""  IMM
 SG_ M2I_Byrack_ReVeEnable_IMM6_22 : 26|2@1+ (1,0) [0|3] ""  IMM
 SG_ Reserved_22 : 28|4@1+ (1,0) [0|15] ""  IMM
 SG_ M2I_Byrack_IsPostTm_IMM6_22 : 32|8@1+ (0.01,0) [0|2.55] "s"  IMM
 SG_ M2I_Byrack_SysABStTm_IMM6_22 : 40|16@1+ (0.01,0) [0|655.35] "s"  IMM
 SG_ Reserved_22 : 56|8@1+ (1,0) [0|255] ""  IMM

BO_ 2332108455 M2I_Byrack_SUMDATA6__23: 8 MBMU
 SG_ CRC_M2I_Byrack_IMM6_23 : 0|8@1+ (1,0) [0|255] ""  IMM
 SG_ M2I_Byrack_HVS_IMM6_23 : 8|16@1+ (0.1,0) [0|6553.5] "v"  IMM
 SG_ M2I_Byrack_Enable_IMM6_23 : 24|2@1+ (1,0) [0|3] ""  IMM
 SG_ M2I_Byrack_ReVeEnable_IMM6_23 : 26|2@1+ (1,0) [0|3] ""  IMM
 SG_ Reserved_23 : 28|4@1+ (1,0) [0|15] ""  IMM
 SG_ M2I_Byrack_IsPostTm_IMM6_23 : 32|8@1+ (0.01,0) [0|2.55] "s"  IMM
 SG_ M2I_Byrack_SysABStTm_IMM6_23 : 40|16@1+ (0.01,0) [0|655.35] "s"  IMM
 SG_ Reserved_23 : 56|8@1+ (1,0) [0|255] ""  IMM

BO_ 2332108456 M2I_Byrack_SUMDATA6__24: 8 MBMU
 SG_ CRC_M2I_Byrack_IMM6_24 : 0|8@1+ (1,0) [0|255] ""  IMM
 SG_ M2I_Byrack_HVS_IMM6_24 : 8|16@1+ (0.1,0) [0|6553.5] "v"  IMM
 SG_ M2I_Byrack_Enable_IMM6_24 : 24|2@1+ (1,0) [0|3] ""  IMM
 SG_ M2I_Byrack_ReVeEnable_IMM6_24 : 26|2@1+ (1,0) [0|3] ""  IMM
 SG_ Reserved_24 : 28|4@1+ (1,0) [0|15] ""  IMM
 SG_ M2I_Byrack_IsPostTm_IMM6_24 : 32|8@1+ (0.01,0) [0|2.55] "s"  IMM
 SG_ M2I_Byrack_SysABStTm_IMM6_24 : 40|16@1+ (0.01,0) [0|655.35] "s"  IMM
 SG_ Reserved_24 : 56|8@1+ (1,0) [0|255] ""  IMM

BO_ 2332108457 M2I_Byrack_SUMDATA6__25: 8 MBMU
 SG_ CRC_M2I_Byrack_IMM6_25 : 0|8@1+ (1,0) [0|255] ""  IMM
 SG_ M2I_Byrack_HVS_IMM6_25 : 8|16@1+ (0.1,0) [0|6553.5] "v"  IMM
 SG_ M2I_Byrack_Enable_IMM6_25 : 24|2@1+ (1,0) [0|3] ""  IMM
 SG_ M2I_Byrack_ReVeEnable_IMM6_25 : 26|2@1+ (1,0) [0|3] ""  IMM
 SG_ Reserved_25 : 28|4@1+ (1,0) [0|15] ""  IMM
 SG_ M2I_Byrack_IsPostTm_IMM6_25 : 32|8@1+ (0.01,0) [0|2.55] "s"  IMM
 SG_ M2I_Byrack_SysABStTm_IMM6_25 : 40|16@1+ (0.01,0) [0|655.35] "s"  IMM
 SG_ Reserved_25 : 56|8@1+ (1,0) [0|255] ""  IMM

BO_ 2332108458 M2I_Byrack_SUMDATA6__26: 8 MBMU
 SG_ CRC_M2I_Byrack_IMM6_26 : 0|8@1+ (1,0) [0|255] ""  IMM
 SG_ M2I_Byrack_HVS_IMM6_26 : 8|16@1+ (0.1,0) [0|6553.5] "v"  IMM
 SG_ M2I_Byrack_Enable_IMM6_26 : 24|2@1+ (1,0) [0|3] ""  IMM
 SG_ M2I_Byrack_ReVeEnable_IMM6_26 : 26|2@1+ (1,0) [0|3] ""  IMM
 SG_ Reserved_26 : 28|4@1+ (1,0) [0|15] ""  IMM
 SG_ M2I_Byrack_IsPostTm_IMM6_26 : 32|8@1+ (0.01,0) [0|2.55] "s"  IMM
 SG_ M2I_Byrack_SysABStTm_IMM6_26 : 40|16@1+ (0.01,0) [0|655.35] "s"  IMM
 SG_ Reserved_26 : 56|8@1+ (1,0) [0|255] ""  IMM

BO_ 2332108459 M2I_Byrack_SUMDATA6__27: 8 MBMU
 SG_ CRC_M2I_Byrack_IMM6_27 : 0|8@1+ (1,0) [0|255] ""  IMM
 SG_ M2I_Byrack_HVS_IMM6_27 : 8|16@1+ (0.1,0) [0|6553.5] "v"  IMM
 SG_ M2I_Byrack_Enable_IMM6_27 : 24|2@1+ (1,0) [0|3] ""  IMM
 SG_ M2I_Byrack_ReVeEnable_IMM6_27 : 26|2@1+ (1,0) [0|3] ""  IMM
 SG_ Reserved_27 : 28|4@1+ (1,0) [0|15] ""  IMM
 SG_ M2I_Byrack_IsPostTm_IMM6_27 : 32|8@1+ (0.01,0) [0|2.55] "s"  IMM
 SG_ M2I_Byrack_SysABStTm_IMM6_27 : 40|16@1+ (0.01,0) [0|655.35] "s"  IMM
 SG_ Reserved_27 : 56|8@1+ (1,0) [0|255] ""  IMM

BO_ 2332108460 M2I_Byrack_SUMDATA6__28: 8 MBMU
 SG_ CRC_M2I_Byrack_IMM6_28 : 0|8@1+ (1,0) [0|255] ""  IMM
 SG_ M2I_Byrack_HVS_IMM6_28 : 8|16@1+ (0.1,0) [0|6553.5] "v"  IMM
 SG_ M2I_Byrack_Enable_IMM6_28 : 24|2@1+ (1,0) [0|3] ""  IMM
 SG_ M2I_Byrack_ReVeEnable_IMM6_28 : 26|2@1+ (1,0) [0|3] ""  IMM
 SG_ Reserved_28 : 28|4@1+ (1,0) [0|15] ""  IMM
 SG_ M2I_Byrack_IsPostTm_IMM6_28 : 32|8@1+ (0.01,0) [0|2.55] "s"  IMM
 SG_ M2I_Byrack_SysABStTm_IMM6_28 : 40|16@1+ (0.01,0) [0|655.35] "s"  IMM
 SG_ Reserved_28 : 56|8@1+ (1,0) [0|255] ""  IMM

BO_ 2332108461 M2I_Byrack_SUMDATA6__29: 8 MBMU
 SG_ CRC_M2I_Byrack_IMM6_29 : 0|8@1+ (1,0) [0|255] ""  IMM
 SG_ M2I_Byrack_HVS_IMM6_29 : 8|16@1+ (0.1,0) [0|6553.5] "v"  IMM
 SG_ M2I_Byrack_Enable_IMM6_29 : 24|2@1+ (1,0) [0|3] ""  IMM
 SG_ M2I_Byrack_ReVeEnable_IMM6_29 : 26|2@1+ (1,0) [0|3] ""  IMM
 SG_ Reserved_29 : 28|4@1+ (1,0) [0|15] ""  IMM
 SG_ M2I_Byrack_IsPostTm_IMM6_29 : 32|8@1+ (0.01,0) [0|2.55] "s"  IMM
 SG_ M2I_Byrack_SysABStTm_IMM6_29 : 40|16@1+ (0.01,0) [0|655.35] "s"  IMM
 SG_ Reserved_29 : 56|8@1+ (1,0) [0|255] ""  IMM

BO_ 2332108462 M2I_Byrack_SUMDATA6__30: 8 MBMU
 SG_ CRC_M2I_Byrack_IMM6_30 : 0|8@1+ (1,0) [0|255] ""  IMM
 SG_ M2I_Byrack_HVS_IMM6_30 : 8|16@1+ (0.1,0) [0|6553.5] "v"  IMM
 SG_ M2I_Byrack_Enable_IMM6_30 : 24|2@1+ (1,0) [0|3] ""  IMM
 SG_ M2I_Byrack_ReVeEnable_IMM6_30 : 26|2@1+ (1,0) [0|3] ""  IMM
 SG_ Reserved_30 : 28|4@1+ (1,0) [0|15] ""  IMM
 SG_ M2I_Byrack_IsPostTm_IMM6_30 : 32|8@1+ (0.01,0) [0|2.55] "s"  IMM
 SG_ M2I_Byrack_SysABStTm_IMM6_30 : 40|16@1+ (0.01,0) [0|655.35] "s"  IMM
 SG_ Reserved_30 : 56|8@1+ (1,0) [0|255] ""  IMM

BO_ 2332108463 M2I_Byrack_SUMDATA6__31: 8 MBMU
 SG_ CRC_M2I_Byrack_IMM6_31 : 0|8@1+ (1,0) [0|255] ""  IMM
 SG_ M2I_Byrack_HVS_IMM6_31 : 8|16@1+ (0.1,0) [0|6553.5] "v"  IMM
 SG_ M2I_Byrack_Enable_IMM6_31 : 24|2@1+ (1,0) [0|3] ""  IMM
 SG_ M2I_Byrack_ReVeEnable_IMM6_31 : 26|2@1+ (1,0) [0|3] ""  IMM
 SG_ Reserved_31 : 28|4@1+ (1,0) [0|15] ""  IMM
 SG_ M2I_Byrack_IsPostTm_IMM6_31 : 32|8@1+ (0.01,0) [0|2.55] "s"  IMM
 SG_ M2I_Byrack_SysABStTm_IMM6_31 : 40|16@1+ (0.01,0) [0|655.35] "s"  IMM
 SG_ Reserved_31 : 56|8@1+ (1,0) [0|255] ""  IMM

BO_ 2332108689 M2I_Byrack_SUMDATA7__01: 8 MBMU
 SG_ CRC_M2I_Byrack_IMM7_01 : 0|8@1+ (1,0) [0|255] ""  IMM
 SG_ M2I_Byrack_HVS_IMM7_01 : 8|16@1+ (0.1,0) [0|6553.5] "v"  IMM
 SG_ M2I_Byrack_Enable_IMM7_01 : 24|2@1+ (1,0) [0|3] ""  IMM
 SG_ M2I_Byrack_ReVeEnable_IMM7_01 : 26|2@1+ (1,0) [0|3] ""  IMM
 SG_ Reserved_01 : 28|4@1+ (1,0) [0|15] ""  IMM
 SG_ M2I_Byrack_IsPostTm_IMM7_01 : 32|8@1+ (0.01,0) [0|2.55] "s"  IMM
 SG_ M2I_Byrack_SysABStTm_IMM7_01 : 40|16@1+ (0.01,0) [0|655.35] "s"  IMM
 SG_ Reserved_01 : 56|8@1+ (1,0) [0|255] ""  IMM

BO_ 2332108690 M2I_Byrack_SUMDATA7__02: 8 MBMU
 SG_ CRC_M2I_Byrack_IMM7_02 : 0|8@1+ (1,0) [0|255] ""  IMM
 SG_ M2I_Byrack_HVS_IMM7_02 : 8|16@1+ (0.1,0) [0|6553.5] "v"  IMM
 SG_ M2I_Byrack_Enable_IMM7_02 : 24|2@1+ (1,0) [0|3] ""  IMM
 SG_ M2I_Byrack_ReVeEnable_IMM7_02 : 26|2@1+ (1,0) [0|3] ""  IMM
 SG_ Reserved_02 : 28|4@1+ (1,0) [0|15] ""  IMM
 SG_ M2I_Byrack_IsPostTm_IMM7_02 : 32|8@1+ (0.01,0) [0|2.55] "s"  IMM
 SG_ M2I_Byrack_SysABStTm_IMM7_02 : 40|16@1+ (0.01,0) [0|655.35] "s"  IMM
 SG_ Reserved_02 : 56|8@1+ (1,0) [0|255] ""  IMM

BO_ 2332108691 M2I_Byrack_SUMDATA7__03: 8 MBMU
 SG_ CRC_M2I_Byrack_IMM7_03 : 0|8@1+ (1,0) [0|255] ""  IMM
 SG_ M2I_Byrack_HVS_IMM7_03 : 8|16@1+ (0.1,0) [0|6553.5] "v"  IMM
 SG_ M2I_Byrack_Enable_IMM7_03 : 24|2@1+ (1,0) [0|3] ""  IMM
 SG_ M2I_Byrack_ReVeEnable_IMM7_03 : 26|2@1+ (1,0) [0|3] ""  IMM
 SG_ Reserved_03 : 28|4@1+ (1,0) [0|15] ""  IMM
 SG_ M2I_Byrack_IsPostTm_IMM7_03 : 32|8@1+ (0.01,0) [0|2.55] "s"  IMM
 SG_ M2I_Byrack_SysABStTm_IMM7_03 : 40|16@1+ (0.01,0) [0|655.35] "s"  IMM
 SG_ Reserved_03 : 56|8@1+ (1,0) [0|255] ""  IMM

BO_ 2332108692 M2I_Byrack_SUMDATA7__04: 8 MBMU
 SG_ CRC_M2I_Byrack_IMM7_04 : 0|8@1+ (1,0) [0|255] ""  IMM
 SG_ M2I_Byrack_HVS_IMM7_04 : 8|16@1+ (0.1,0) [0|6553.5] "v"  IMM
 SG_ M2I_Byrack_Enable_IMM7_04 : 24|2@1+ (1,0) [0|3] ""  IMM
 SG_ M2I_Byrack_ReVeEnable_IMM7_04 : 26|2@1+ (1,0) [0|3] ""  IMM
 SG_ Reserved_04 : 28|4@1+ (1,0) [0|15] ""  IMM
 SG_ M2I_Byrack_IsPostTm_IMM7_04 : 32|8@1+ (0.01,0) [0|2.55] "s"  IMM
 SG_ M2I_Byrack_SysABStTm_IMM7_04 : 40|16@1+ (0.01,0) [0|655.35] "s"  IMM
 SG_ Reserved_04 : 56|8@1+ (1,0) [0|255] ""  IMM

BO_ 2332108693 M2I_Byrack_SUMDATA7__05: 8 MBMU
 SG_ CRC_M2I_Byrack_IMM7_05 : 0|8@1+ (1,0) [0|255] ""  IMM
 SG_ M2I_Byrack_HVS_IMM7_05 : 8|16@1+ (0.1,0) [0|6553.5] "v"  IMM
 SG_ M2I_Byrack_Enable_IMM7_05 : 24|2@1+ (1,0) [0|3] ""  IMM
 SG_ M2I_Byrack_ReVeEnable_IMM7_05 : 26|2@1+ (1,0) [0|3] ""  IMM
 SG_ Reserved_05 : 28|4@1+ (1,0) [0|15] ""  IMM
 SG_ M2I_Byrack_IsPostTm_IMM7_05 : 32|8@1+ (0.01,0) [0|2.55] "s"  IMM
 SG_ M2I_Byrack_SysABStTm_IMM7_05 : 40|16@1+ (0.01,0) [0|655.35] "s"  IMM
 SG_ Reserved_05 : 56|8@1+ (1,0) [0|255] ""  IMM

BO_ 2332108694 M2I_Byrack_SUMDATA7__06: 8 MBMU
 SG_ CRC_M2I_Byrack_IMM7_06 : 0|8@1+ (1,0) [0|255] ""  IMM
 SG_ M2I_Byrack_HVS_IMM7_06 : 8|16@1+ (0.1,0) [0|6553.5] "v"  IMM
 SG_ M2I_Byrack_Enable_IMM7_06 : 24|2@1+ (1,0) [0|3] ""  IMM
 SG_ M2I_Byrack_ReVeEnable_IMM7_06 : 26|2@1+ (1,0) [0|3] ""  IMM
 SG_ Reserved_06 : 28|4@1+ (1,0) [0|15] ""  IMM
 SG_ M2I_Byrack_IsPostTm_IMM7_06 : 32|8@1+ (0.01,0) [0|2.55] "s"  IMM
 SG_ M2I_Byrack_SysABStTm_IMM7_06 : 40|16@1+ (0.01,0) [0|655.35] "s"  IMM
 SG_ Reserved_06 : 56|8@1+ (1,0) [0|255] ""  IMM

BO_ 2332108695 M2I_Byrack_SUMDATA7__07: 8 MBMU
 SG_ CRC_M2I_Byrack_IMM7_07 : 0|8@1+ (1,0) [0|255] ""  IMM
 SG_ M2I_Byrack_HVS_IMM7_07 : 8|16@1+ (0.1,0) [0|6553.5] "v"  IMM
 SG_ M2I_Byrack_Enable_IMM7_07 : 24|2@1+ (1,0) [0|3] ""  IMM
 SG_ M2I_Byrack_ReVeEnable_IMM7_07 : 26|2@1+ (1,0) [0|3] ""  IMM
 SG_ Reserved_07 : 28|4@1+ (1,0) [0|15] ""  IMM
 SG_ M2I_Byrack_IsPostTm_IMM7_07 : 32|8@1+ (0.01,0) [0|2.55] "s"  IMM
 SG_ M2I_Byrack_SysABStTm_IMM7_07 : 40|16@1+ (0.01,0) [0|655.35] "s"  IMM
 SG_ Reserved_07 : 56|8@1+ (1,0) [0|255] ""  IMM

BO_ 2332108696 M2I_Byrack_SUMDATA7__08: 8 MBMU
 SG_ CRC_M2I_Byrack_IMM7_08 : 0|8@1+ (1,0) [0|255] ""  IMM
 SG_ M2I_Byrack_HVS_IMM7_08 : 8|16@1+ (0.1,0) [0|6553.5] "v"  IMM
 SG_ M2I_Byrack_Enable_IMM7_08 : 24|2@1+ (1,0) [0|3] ""  IMM
 SG_ M2I_Byrack_ReVeEnable_IMM7_08 : 26|2@1+ (1,0) [0|3] ""  IMM
 SG_ Reserved_08 : 28|4@1+ (1,0) [0|15] ""  IMM
 SG_ M2I_Byrack_IsPostTm_IMM7_08 : 32|8@1+ (0.01,0) [0|2.55] "s"  IMM
 SG_ M2I_Byrack_SysABStTm_IMM7_08 : 40|16@1+ (0.01,0) [0|655.35] "s"  IMM
 SG_ Reserved_08 : 56|8@1+ (1,0) [0|255] ""  IMM

BO_ 2332108697 M2I_Byrack_SUMDATA7__09: 8 MBMU
 SG_ CRC_M2I_Byrack_IMM7_09 : 0|8@1+ (1,0) [0|255] ""  IMM
 SG_ M2I_Byrack_HVS_IMM7_09 : 8|16@1+ (0.1,0) [0|6553.5] "v"  IMM
 SG_ M2I_Byrack_Enable_IMM7_09 : 24|2@1+ (1,0) [0|3] ""  IMM
 SG_ M2I_Byrack_ReVeEnable_IMM7_09 : 26|2@1+ (1,0) [0|3] ""  IMM
 SG_ Reserved_09 : 28|4@1+ (1,0) [0|15] ""  IMM
 SG_ M2I_Byrack_IsPostTm_IMM7_09 : 32|8@1+ (0.01,0) [0|2.55] "s"  IMM
 SG_ M2I_Byrack_SysABStTm_IMM7_09 : 40|16@1+ (0.01,0) [0|655.35] "s"  IMM
 SG_ Reserved_09 : 56|8@1+ (1,0) [0|255] ""  IMM

BO_ 2332108698 M2I_Byrack_SUMDATA7__10: 8 MBMU
 SG_ CRC_M2I_Byrack_IMM7_10 : 0|8@1+ (1,0) [0|255] ""  IMM
 SG_ M2I_Byrack_HVS_IMM7_10 : 8|16@1+ (0.1,0) [0|6553.5] "v"  IMM
 SG_ M2I_Byrack_Enable_IMM7_10 : 24|2@1+ (1,0) [0|3] ""  IMM
 SG_ M2I_Byrack_ReVeEnable_IMM7_10 : 26|2@1+ (1,0) [0|3] ""  IMM
 SG_ Reserved_10 : 28|4@1+ (1,0) [0|15] ""  IMM
 SG_ M2I_Byrack_IsPostTm_IMM7_10 : 32|8@1+ (0.01,0) [0|2.55] "s"  IMM
 SG_ M2I_Byrack_SysABStTm_IMM7_10 : 40|16@1+ (0.01,0) [0|655.35] "s"  IMM
 SG_ Reserved_10 : 56|8@1+ (1,0) [0|255] ""  IMM

BO_ 2332108699 M2I_Byrack_SUMDATA7__11: 8 MBMU
 SG_ CRC_M2I_Byrack_IMM7_11 : 0|8@1+ (1,0) [0|255] ""  IMM
 SG_ M2I_Byrack_HVS_IMM7_11 : 8|16@1+ (0.1,0) [0|6553.5] "v"  IMM
 SG_ M2I_Byrack_Enable_IMM7_11 : 24|2@1+ (1,0) [0|3] ""  IMM
 SG_ M2I_Byrack_ReVeEnable_IMM7_11 : 26|2@1+ (1,0) [0|3] ""  IMM
 SG_ Reserved_11 : 28|4@1+ (1,0) [0|15] ""  IMM
 SG_ M2I_Byrack_IsPostTm_IMM7_11 : 32|8@1+ (0.01,0) [0|2.55] "s"  IMM
 SG_ M2I_Byrack_SysABStTm_IMM7_11 : 40|16@1+ (0.01,0) [0|655.35] "s"  IMM
 SG_ Reserved_11 : 56|8@1+ (1,0) [0|255] ""  IMM

BO_ 2332108700 M2I_Byrack_SUMDATA7__12: 8 MBMU
 SG_ CRC_M2I_Byrack_IMM7_12 : 0|8@1+ (1,0) [0|255] ""  IMM
 SG_ M2I_Byrack_HVS_IMM7_12 : 8|16@1+ (0.1,0) [0|6553.5] "v"  IMM
 SG_ M2I_Byrack_Enable_IMM7_12 : 24|2@1+ (1,0) [0|3] ""  IMM
 SG_ M2I_Byrack_ReVeEnable_IMM7_12 : 26|2@1+ (1,0) [0|3] ""  IMM
 SG_ Reserved_12 : 28|4@1+ (1,0) [0|15] ""  IMM
 SG_ M2I_Byrack_IsPostTm_IMM7_12 : 32|8@1+ (0.01,0) [0|2.55] "s"  IMM
 SG_ M2I_Byrack_SysABStTm_IMM7_12 : 40|16@1+ (0.01,0) [0|655.35] "s"  IMM
 SG_ Reserved_12 : 56|8@1+ (1,0) [0|255] ""  IMM

BO_ 2332108701 M2I_Byrack_SUMDATA7__13: 8 MBMU
 SG_ CRC_M2I_Byrack_IMM7_13 : 0|8@1+ (1,0) [0|255] ""  IMM
 SG_ M2I_Byrack_HVS_IMM7_13 : 8|16@1+ (0.1,0) [0|6553.5] "v"  IMM
 SG_ M2I_Byrack_Enable_IMM7_13 : 24|2@1+ (1,0) [0|3] ""  IMM
 SG_ M2I_Byrack_ReVeEnable_IMM7_13 : 26|2@1+ (1,0) [0|3] ""  IMM
 SG_ Reserved_13 : 28|4@1+ (1,0) [0|15] ""  IMM
 SG_ M2I_Byrack_IsPostTm_IMM7_13 : 32|8@1+ (0.01,0) [0|2.55] "s"  IMM
 SG_ M2I_Byrack_SysABStTm_IMM7_13 : 40|16@1+ (0.01,0) [0|655.35] "s"  IMM
 SG_ Reserved_13 : 56|8@1+ (1,0) [0|255] ""  IMM

BO_ 2332108702 M2I_Byrack_SUMDATA7__14: 8 MBMU
 SG_ CRC_M2I_Byrack_IMM7_14 : 0|8@1+ (1,0) [0|255] ""  IMM
 SG_ M2I_Byrack_HVS_IMM7_14 : 8|16@1+ (0.1,0) [0|6553.5] "v"  IMM
 SG_ M2I_Byrack_Enable_IMM7_14 : 24|2@1+ (1,0) [0|3] ""  IMM
 SG_ M2I_Byrack_ReVeEnable_IMM7_14 : 26|2@1+ (1,0) [0|3] ""  IMM
 SG_ Reserved_14 : 28|4@1+ (1,0) [0|15] ""  IMM
 SG_ M2I_Byrack_IsPostTm_IMM7_14 : 32|8@1+ (0.01,0) [0|2.55] "s"  IMM
 SG_ M2I_Byrack_SysABStTm_IMM7_14 : 40|16@1+ (0.01,0) [0|655.35] "s"  IMM
 SG_ Reserved_14 : 56|8@1+ (1,0) [0|255] ""  IMM

BO_ 2332108703 M2I_Byrack_SUMDATA7__15: 8 MBMU
 SG_ CRC_M2I_Byrack_IMM7_15 : 0|8@1+ (1,0) [0|255] ""  IMM
 SG_ M2I_Byrack_HVS_IMM7_15 : 8|16@1+ (0.1,0) [0|6553.5] "v"  IMM
 SG_ M2I_Byrack_Enable_IMM7_15 : 24|2@1+ (1,0) [0|3] ""  IMM
 SG_ M2I_Byrack_ReVeEnable_IMM7_15 : 26|2@1+ (1,0) [0|3] ""  IMM
 SG_ Reserved_15 : 28|4@1+ (1,0) [0|15] ""  IMM
 SG_ M2I_Byrack_IsPostTm_IMM7_15 : 32|8@1+ (0.01,0) [0|2.55] "s"  IMM
 SG_ M2I_Byrack_SysABStTm_IMM7_15 : 40|16@1+ (0.01,0) [0|655.35] "s"  IMM
 SG_ Reserved_15 : 56|8@1+ (1,0) [0|255] ""  IMM

BO_ 2332108704 M2I_Byrack_SUMDATA7__16: 8 MBMU
 SG_ CRC_M2I_Byrack_IMM7_16 : 0|8@1+ (1,0) [0|255] ""  IMM
 SG_ M2I_Byrack_HVS_IMM7_16 : 8|16@1+ (0.1,0) [0|6553.5] "v"  IMM
 SG_ M2I_Byrack_Enable_IMM7_16 : 24|2@1+ (1,0) [0|3] ""  IMM
 SG_ M2I_Byrack_ReVeEnable_IMM7_16 : 26|2@1+ (1,0) [0|3] ""  IMM
 SG_ Reserved_16 : 28|4@1+ (1,0) [0|15] ""  IMM
 SG_ M2I_Byrack_IsPostTm_IMM7_16 : 32|8@1+ (0.01,0) [0|2.55] "s"  IMM
 SG_ M2I_Byrack_SysABStTm_IMM7_16 : 40|16@1+ (0.01,0) [0|655.35] "s"  IMM
 SG_ Reserved_16 : 56|8@1+ (1,0) [0|255] ""  IMM

BO_ 2332108705 M2I_Byrack_SUMDATA7__17: 8 MBMU
 SG_ CRC_M2I_Byrack_IMM7_17 : 0|8@1+ (1,0) [0|255] ""  IMM
 SG_ M2I_Byrack_HVS_IMM7_17 : 8|16@1+ (0.1,0) [0|6553.5] "v"  IMM
 SG_ M2I_Byrack_Enable_IMM7_17 : 24|2@1+ (1,0) [0|3] ""  IMM
 SG_ M2I_Byrack_ReVeEnable_IMM7_17 : 26|2@1+ (1,0) [0|3] ""  IMM
 SG_ Reserved_17 : 28|4@1+ (1,0) [0|15] ""  IMM
 SG_ M2I_Byrack_IsPostTm_IMM7_17 : 32|8@1+ (0.01,0) [0|2.55] "s"  IMM
 SG_ M2I_Byrack_SysABStTm_IMM7_17 : 40|16@1+ (0.01,0) [0|655.35] "s"  IMM
 SG_ Reserved_17 : 56|8@1+ (1,0) [0|255] ""  IMM

BO_ 2332108706 M2I_Byrack_SUMDATA7__18: 8 MBMU
 SG_ CRC_M2I_Byrack_IMM7_18 : 0|8@1+ (1,0) [0|255] ""  IMM
 SG_ M2I_Byrack_HVS_IMM7_18 : 8|16@1+ (0.1,0) [0|6553.5] "v"  IMM
 SG_ M2I_Byrack_Enable_IMM7_18 : 24|2@1+ (1,0) [0|3] ""  IMM
 SG_ M2I_Byrack_ReVeEnable_IMM7_18 : 26|2@1+ (1,0) [0|3] ""  IMM
 SG_ Reserved_18 : 28|4@1+ (1,0) [0|15] ""  IMM
 SG_ M2I_Byrack_IsPostTm_IMM7_18 : 32|8@1+ (0.01,0) [0|2.55] "s"  IMM
 SG_ M2I_Byrack_SysABStTm_IMM7_18 : 40|16@1+ (0.01,0) [0|655.35] "s"  IMM
 SG_ Reserved_18 : 56|8@1+ (1,0) [0|255] ""  IMM

BO_ 2332108707 M2I_Byrack_SUMDATA7__19: 8 MBMU
 SG_ CRC_M2I_Byrack_IMM7_19 : 0|8@1+ (1,0) [0|255] ""  IMM
 SG_ M2I_Byrack_HVS_IMM7_19 : 8|16@1+ (0.1,0) [0|6553.5] "v"  IMM
 SG_ M2I_Byrack_Enable_IMM7_19 : 24|2@1+ (1,0) [0|3] ""  IMM
 SG_ M2I_Byrack_ReVeEnable_IMM7_19 : 26|2@1+ (1,0) [0|3] ""  IMM
 SG_ Reserved_19 : 28|4@1+ (1,0) [0|15] ""  IMM
 SG_ M2I_Byrack_IsPostTm_IMM7_19 : 32|8@1+ (0.01,0) [0|2.55] "s"  IMM
 SG_ M2I_Byrack_SysABStTm_IMM7_19 : 40|16@1+ (0.01,0) [0|655.35] "s"  IMM
 SG_ Reserved_19 : 56|8@1+ (1,0) [0|255] ""  IMM

BO_ 2332108708 M2I_Byrack_SUMDATA7__20: 8 MBMU
 SG_ CRC_M2I_Byrack_IMM7_20 : 0|8@1+ (1,0) [0|255] ""  IMM
 SG_ M2I_Byrack_HVS_IMM7_20 : 8|16@1+ (0.1,0) [0|6553.5] "v"  IMM
 SG_ M2I_Byrack_Enable_IMM7_20 : 24|2@1+ (1,0) [0|3] ""  IMM
 SG_ M2I_Byrack_ReVeEnable_IMM7_20 : 26|2@1+ (1,0) [0|3] ""  IMM
 SG_ Reserved_20 : 28|4@1+ (1,0) [0|15] ""  IMM
 SG_ M2I_Byrack_IsPostTm_IMM7_20 : 32|8@1+ (0.01,0) [0|2.55] "s"  IMM
 SG_ M2I_Byrack_SysABStTm_IMM7_20 : 40|16@1+ (0.01,0) [0|655.35] "s"  IMM
 SG_ Reserved_20 : 56|8@1+ (1,0) [0|255] ""  IMM

BO_ 2332108709 M2I_Byrack_SUMDATA7__21: 8 MBMU
 SG_ CRC_M2I_Byrack_IMM7_21 : 0|8@1+ (1,0) [0|255] ""  IMM
 SG_ M2I_Byrack_HVS_IMM7_21 : 8|16@1+ (0.1,0) [0|6553.5] "v"  IMM
 SG_ M2I_Byrack_Enable_IMM7_21 : 24|2@1+ (1,0) [0|3] ""  IMM
 SG_ M2I_Byrack_ReVeEnable_IMM7_21 : 26|2@1+ (1,0) [0|3] ""  IMM
 SG_ Reserved_21 : 28|4@1+ (1,0) [0|15] ""  IMM
 SG_ M2I_Byrack_IsPostTm_IMM7_21 : 32|8@1+ (0.01,0) [0|2.55] "s"  IMM
 SG_ M2I_Byrack_SysABStTm_IMM7_21 : 40|16@1+ (0.01,0) [0|655.35] "s"  IMM
 SG_ Reserved_21 : 56|8@1+ (1,0) [0|255] ""  IMM

BO_ 2332108710 M2I_Byrack_SUMDATA7__22: 8 MBMU
 SG_ CRC_M2I_Byrack_IMM7_22 : 0|8@1+ (1,0) [0|255] ""  IMM
 SG_ M2I_Byrack_HVS_IMM7_22 : 8|16@1+ (0.1,0) [0|6553.5] "v"  IMM
 SG_ M2I_Byrack_Enable_IMM7_22 : 24|2@1+ (1,0) [0|3] ""  IMM
 SG_ M2I_Byrack_ReVeEnable_IMM7_22 : 26|2@1+ (1,0) [0|3] ""  IMM
 SG_ Reserved_22 : 28|4@1+ (1,0) [0|15] ""  IMM
 SG_ M2I_Byrack_IsPostTm_IMM7_22 : 32|8@1+ (0.01,0) [0|2.55] "s"  IMM
 SG_ M2I_Byrack_SysABStTm_IMM7_22 : 40|16@1+ (0.01,0) [0|655.35] "s"  IMM
 SG_ Reserved_22 : 56|8@1+ (1,0) [0|255] ""  IMM

BO_ 2332108711 M2I_Byrack_SUMDATA7__23: 8 MBMU
 SG_ CRC_M2I_Byrack_IMM7_23 : 0|8@1+ (1,0) [0|255] ""  IMM
 SG_ M2I_Byrack_HVS_IMM7_23 : 8|16@1+ (0.1,0) [0|6553.5] "v"  IMM
 SG_ M2I_Byrack_Enable_IMM7_23 : 24|2@1+ (1,0) [0|3] ""  IMM
 SG_ M2I_Byrack_ReVeEnable_IMM7_23 : 26|2@1+ (1,0) [0|3] ""  IMM
 SG_ Reserved_23 : 28|4@1+ (1,0) [0|15] ""  IMM
 SG_ M2I_Byrack_IsPostTm_IMM7_23 : 32|8@1+ (0.01,0) [0|2.55] "s"  IMM
 SG_ M2I_Byrack_SysABStTm_IMM7_23 : 40|16@1+ (0.01,0) [0|655.35] "s"  IMM
 SG_ Reserved_23 : 56|8@1+ (1,0) [0|255] ""  IMM

BO_ 2332108712 M2I_Byrack_SUMDATA7__24: 8 MBMU
 SG_ CRC_M2I_Byrack_IMM7_24 : 0|8@1+ (1,0) [0|255] ""  IMM
 SG_ M2I_Byrack_HVS_IMM7_24 : 8|16@1+ (0.1,0) [0|6553.5] "v"  IMM
 SG_ M2I_Byrack_Enable_IMM7_24 : 24|2@1+ (1,0) [0|3] ""  IMM
 SG_ M2I_Byrack_ReVeEnable_IMM7_24 : 26|2@1+ (1,0) [0|3] ""  IMM
 SG_ Reserved_24 : 28|4@1+ (1,0) [0|15] ""  IMM
 SG_ M2I_Byrack_IsPostTm_IMM7_24 : 32|8@1+ (0.01,0) [0|2.55] "s"  IMM
 SG_ M2I_Byrack_SysABStTm_IMM7_24 : 40|16@1+ (0.01,0) [0|655.35] "s"  IMM
 SG_ Reserved_24 : 56|8@1+ (1,0) [0|255] ""  IMM

BO_ 2332108713 M2I_Byrack_SUMDATA7__25: 8 MBMU
 SG_ CRC_M2I_Byrack_IMM7_25 : 0|8@1+ (1,0) [0|255] ""  IMM
 SG_ M2I_Byrack_HVS_IMM7_25 : 8|16@1+ (0.1,0) [0|6553.5] "v"  IMM
 SG_ M2I_Byrack_Enable_IMM7_25 : 24|2@1+ (1,0) [0|3] ""  IMM
 SG_ M2I_Byrack_ReVeEnable_IMM7_25 : 26|2@1+ (1,0) [0|3] ""  IMM
 SG_ Reserved_25 : 28|4@1+ (1,0) [0|15] ""  IMM
 SG_ M2I_Byrack_IsPostTm_IMM7_25 : 32|8@1+ (0.01,0) [0|2.55] "s"  IMM
 SG_ M2I_Byrack_SysABStTm_IMM7_25 : 40|16@1+ (0.01,0) [0|655.35] "s"  IMM
 SG_ Reserved_25 : 56|8@1+ (1,0) [0|255] ""  IMM

BO_ 2332108714 M2I_Byrack_SUMDATA7__26: 8 MBMU
 SG_ CRC_M2I_Byrack_IMM7_26 : 0|8@1+ (1,0) [0|255] ""  IMM
 SG_ M2I_Byrack_HVS_IMM7_26 : 8|16@1+ (0.1,0) [0|6553.5] "v"  IMM
 SG_ M2I_Byrack_Enable_IMM7_26 : 24|2@1+ (1,0) [0|3] ""  IMM
 SG_ M2I_Byrack_ReVeEnable_IMM7_26 : 26|2@1+ (1,0) [0|3] ""  IMM
 SG_ Reserved_26 : 28|4@1+ (1,0) [0|15] ""  IMM
 SG_ M2I_Byrack_IsPostTm_IMM7_26 : 32|8@1+ (0.01,0) [0|2.55] "s"  IMM
 SG_ M2I_Byrack_SysABStTm_IMM7_26 : 40|16@1+ (0.01,0) [0|655.35] "s"  IMM
 SG_ Reserved_26 : 56|8@1+ (1,0) [0|255] ""  IMM

BO_ 2332108715 M2I_Byrack_SUMDATA7__27: 8 MBMU
 SG_ CRC_M2I_Byrack_IMM7_27 : 0|8@1+ (1,0) [0|255] ""  IMM
 SG_ M2I_Byrack_HVS_IMM7_27 : 8|16@1+ (0.1,0) [0|6553.5] "v"  IMM
 SG_ M2I_Byrack_Enable_IMM7_27 : 24|2@1+ (1,0) [0|3] ""  IMM
 SG_ M2I_Byrack_ReVeEnable_IMM7_27 : 26|2@1+ (1,0) [0|3] ""  IMM
 SG_ Reserved_27 : 28|4@1+ (1,0) [0|15] ""  IMM
 SG_ M2I_Byrack_IsPostTm_IMM7_27 : 32|8@1+ (0.01,0) [0|2.55] "s"  IMM
 SG_ M2I_Byrack_SysABStTm_IMM7_27 : 40|16@1+ (0.01,0) [0|655.35] "s"  IMM
 SG_ Reserved_27 : 56|8@1+ (1,0) [0|255] ""  IMM

BO_ 2332108716 M2I_Byrack_SUMDATA7__28: 8 MBMU
 SG_ CRC_M2I_Byrack_IMM7_28 : 0|8@1+ (1,0) [0|255] ""  IMM
 SG_ M2I_Byrack_HVS_IMM7_28 : 8|16@1+ (0.1,0) [0|6553.5] "v"  IMM
 SG_ M2I_Byrack_Enable_IMM7_28 : 24|2@1+ (1,0) [0|3] ""  IMM
 SG_ M2I_Byrack_ReVeEnable_IMM7_28 : 26|2@1+ (1,0) [0|3] ""  IMM
 SG_ Reserved_28 : 28|4@1+ (1,0) [0|15] ""  IMM
 SG_ M2I_Byrack_IsPostTm_IMM7_28 : 32|8@1+ (0.01,0) [0|2.55] "s"  IMM
 SG_ M2I_Byrack_SysABStTm_IMM7_28 : 40|16@1+ (0.01,0) [0|655.35] "s"  IMM
 SG_ Reserved_28 : 56|8@1+ (1,0) [0|255] ""  IMM

BO_ 2332108717 M2I_Byrack_SUMDATA7__29: 8 MBMU
 SG_ CRC_M2I_Byrack_IMM7_29 : 0|8@1+ (1,0) [0|255] ""  IMM
 SG_ M2I_Byrack_HVS_IMM7_29 : 8|16@1+ (0.1,0) [0|6553.5] "v"  IMM
 SG_ M2I_Byrack_Enable_IMM7_29 : 24|2@1+ (1,0) [0|3] ""  IMM
 SG_ M2I_Byrack_ReVeEnable_IMM7_29 : 26|2@1+ (1,0) [0|3] ""  IMM
 SG_ Reserved_29 : 28|4@1+ (1,0) [0|15] ""  IMM
 SG_ M2I_Byrack_IsPostTm_IMM7_29 : 32|8@1+ (0.01,0) [0|2.55] "s"  IMM
 SG_ M2I_Byrack_SysABStTm_IMM7_29 : 40|16@1+ (0.01,0) [0|655.35] "s"  IMM
 SG_ Reserved_29 : 56|8@1+ (1,0) [0|255] ""  IMM

BO_ 2332108718 M2I_Byrack_SUMDATA7__30: 8 MBMU
 SG_ CRC_M2I_Byrack_IMM7_30 : 0|8@1+ (1,0) [0|255] ""  IMM
 SG_ M2I_Byrack_HVS_IMM7_30 : 8|16@1+ (0.1,0) [0|6553.5] "v"  IMM
 SG_ M2I_Byrack_Enable_IMM7_30 : 24|2@1+ (1,0) [0|3] ""  IMM
 SG_ M2I_Byrack_ReVeEnable_IMM7_30 : 26|2@1+ (1,0) [0|3] ""  IMM
 SG_ Reserved_30 : 28|4@1+ (1,0) [0|15] ""  IMM
 SG_ M2I_Byrack_IsPostTm_IMM7_30 : 32|8@1+ (0.01,0) [0|2.55] "s"  IMM
 SG_ M2I_Byrack_SysABStTm_IMM7_30 : 40|16@1+ (0.01,0) [0|655.35] "s"  IMM
 SG_ Reserved_30 : 56|8@1+ (1,0) [0|255] ""  IMM

BO_ 2332108719 M2I_Byrack_SUMDATA7__31: 8 MBMU
 SG_ CRC_M2I_Byrack_IMM7_31 : 0|8@1+ (1,0) [0|255] ""  IMM
 SG_ M2I_Byrack_HVS_IMM7_31 : 8|16@1+ (0.1,0) [0|6553.5] "v"  IMM
 SG_ M2I_Byrack_Enable_IMM7_31 : 24|2@1+ (1,0) [0|3] ""  IMM
 SG_ M2I_Byrack_ReVeEnable_IMM7_31 : 26|2@1+ (1,0) [0|3] ""  IMM
 SG_ Reserved_31 : 28|4@1+ (1,0) [0|15] ""  IMM
 SG_ M2I_Byrack_IsPostTm_IMM7_31 : 32|8@1+ (0.01,0) [0|2.55] "s"  IMM
 SG_ M2I_Byrack_SysABStTm_IMM7_31 : 40|16@1+ (0.01,0) [0|655.35] "s"  IMM
 SG_ Reserved_31 : 56|8@1+ (1,0) [0|255] ""  IMM

BO_ 2332108945 M2I_Byrack_SUMDATA8__01: 8 MBMU
 SG_ CRC_M2I_Byrack_IMM8_01 : 0|8@1+ (1,0) [0|255] ""  IMM
 SG_ M2I_Byrack_HVS_IMM8_01 : 8|16@1+ (0.1,0) [0|6553.5] "v"  IMM
 SG_ M2I_Byrack_Enable_IMM8_01 : 24|2@1+ (1,0) [0|3] ""  IMM
 SG_ M2I_Byrack_ReVeEnable_IMM8_01 : 26|2@1+ (1,0) [0|3] ""  IMM
 SG_ Reserved_01 : 28|4@1+ (1,0) [0|15] ""  IMM
 SG_ M2I_Byrack_IsPostTm_IMM8_01 : 32|8@1+ (0.01,0) [0|2.55] "s"  IMM
 SG_ M2I_Byrack_SysABStTm_IMM8_01 : 40|16@1+ (0.01,0) [0|655.35] "s"  IMM
 SG_ Reserved_01 : 56|8@1+ (1,0) [0|255] ""  IMM

BO_ 2332108946 M2I_Byrack_SUMDATA8__02: 8 MBMU
 SG_ CRC_M2I_Byrack_IMM8_02 : 0|8@1+ (1,0) [0|255] ""  IMM
 SG_ M2I_Byrack_HVS_IMM8_02 : 8|16@1+ (0.1,0) [0|6553.5] "v"  IMM
 SG_ M2I_Byrack_Enable_IMM8_02 : 24|2@1+ (1,0) [0|3] ""  IMM
 SG_ M2I_Byrack_ReVeEnable_IMM8_02 : 26|2@1+ (1,0) [0|3] ""  IMM
 SG_ Reserved_02 : 28|4@1+ (1,0) [0|15] ""  IMM
 SG_ M2I_Byrack_IsPostTm_IMM8_02 : 32|8@1+ (0.01,0) [0|2.55] "s"  IMM
 SG_ M2I_Byrack_SysABStTm_IMM8_02 : 40|16@1+ (0.01,0) [0|655.35] "s"  IMM
 SG_ Reserved_02 : 56|8@1+ (1,0) [0|255] ""  IMM

BO_ 2332108947 M2I_Byrack_SUMDATA8__03: 8 MBMU
 SG_ CRC_M2I_Byrack_IMM8_03 : 0|8@1+ (1,0) [0|255] ""  IMM
 SG_ M2I_Byrack_HVS_IMM8_03 : 8|16@1+ (0.1,0) [0|6553.5] "v"  IMM
 SG_ M2I_Byrack_Enable_IMM8_03 : 24|2@1+ (1,0) [0|3] ""  IMM
 SG_ M2I_Byrack_ReVeEnable_IMM8_03 : 26|2@1+ (1,0) [0|3] ""  IMM
 SG_ Reserved_03 : 28|4@1+ (1,0) [0|15] ""  IMM
 SG_ M2I_Byrack_IsPostTm_IMM8_03 : 32|8@1+ (0.01,0) [0|2.55] "s"  IMM
 SG_ M2I_Byrack_SysABStTm_IMM8_03 : 40|16@1+ (0.01,0) [0|655.35] "s"  IMM
 SG_ Reserved_03 : 56|8@1+ (1,0) [0|255] ""  IMM

BO_ 2332108948 M2I_Byrack_SUMDATA8__04: 8 MBMU
 SG_ CRC_M2I_Byrack_IMM8_04 : 0|8@1+ (1,0) [0|255] ""  IMM
 SG_ M2I_Byrack_HVS_IMM8_04 : 8|16@1+ (0.1,0) [0|6553.5] "v"  IMM
 SG_ M2I_Byrack_Enable_IMM8_04 : 24|2@1+ (1,0) [0|3] ""  IMM
 SG_ M2I_Byrack_ReVeEnable_IMM8_04 : 26|2@1+ (1,0) [0|3] ""  IMM
 SG_ Reserved_04 : 28|4@1+ (1,0) [0|15] ""  IMM
 SG_ M2I_Byrack_IsPostTm_IMM8_04 : 32|8@1+ (0.01,0) [0|2.55] "s"  IMM
 SG_ M2I_Byrack_SysABStTm_IMM8_04 : 40|16@1+ (0.01,0) [0|655.35] "s"  IMM
 SG_ Reserved_04 : 56|8@1+ (1,0) [0|255] ""  IMM

BO_ 2332108949 M2I_Byrack_SUMDATA8__05: 8 MBMU
 SG_ CRC_M2I_Byrack_IMM8_05 : 0|8@1+ (1,0) [0|255] ""  IMM
 SG_ M2I_Byrack_HVS_IMM8_05 : 8|16@1+ (0.1,0) [0|6553.5] "v"  IMM
 SG_ M2I_Byrack_Enable_IMM8_05 : 24|2@1+ (1,0) [0|3] ""  IMM
 SG_ M2I_Byrack_ReVeEnable_IMM8_05 : 26|2@1+ (1,0) [0|3] ""  IMM
 SG_ Reserved_05 : 28|4@1+ (1,0) [0|15] ""  IMM
 SG_ M2I_Byrack_IsPostTm_IMM8_05 : 32|8@1+ (0.01,0) [0|2.55] "s"  IMM
 SG_ M2I_Byrack_SysABStTm_IMM8_05 : 40|16@1+ (0.01,0) [0|655.35] "s"  IMM
 SG_ Reserved_05 : 56|8@1+ (1,0) [0|255] ""  IMM

BO_ 2332108950 M2I_Byrack_SUMDATA8__06: 8 MBMU
 SG_ CRC_M2I_Byrack_IMM8_06 : 0|8@1+ (1,0) [0|255] ""  IMM
 SG_ M2I_Byrack_HVS_IMM8_06 : 8|16@1+ (0.1,0) [0|6553.5] "v"  IMM
 SG_ M2I_Byrack_Enable_IMM8_06 : 24|2@1+ (1,0) [0|3] ""  IMM
 SG_ M2I_Byrack_ReVeEnable_IMM8_06 : 26|2@1+ (1,0) [0|3] ""  IMM
 SG_ Reserved_06 : 28|4@1+ (1,0) [0|15] ""  IMM
 SG_ M2I_Byrack_IsPostTm_IMM8_06 : 32|8@1+ (0.01,0) [0|2.55] "s"  IMM
 SG_ M2I_Byrack_SysABStTm_IMM8_06 : 40|16@1+ (0.01,0) [0|655.35] "s"  IMM
 SG_ Reserved_06 : 56|8@1+ (1,0) [0|255] ""  IMM

BO_ 2332108951 M2I_Byrack_SUMDATA8__07: 8 MBMU
 SG_ CRC_M2I_Byrack_IMM8_07 : 0|8@1+ (1,0) [0|255] ""  IMM
 SG_ M2I_Byrack_HVS_IMM8_07 : 8|16@1+ (0.1,0) [0|6553.5] "v"  IMM
 SG_ M2I_Byrack_Enable_IMM8_07 : 24|2@1+ (1,0) [0|3] ""  IMM
 SG_ M2I_Byrack_ReVeEnable_IMM8_07 : 26|2@1+ (1,0) [0|3] ""  IMM
 SG_ Reserved_07 : 28|4@1+ (1,0) [0|15] ""  IMM
 SG_ M2I_Byrack_IsPostTm_IMM8_07 : 32|8@1+ (0.01,0) [0|2.55] "s"  IMM
 SG_ M2I_Byrack_SysABStTm_IMM8_07 : 40|16@1+ (0.01,0) [0|655.35] "s"  IMM
 SG_ Reserved_07 : 56|8@1+ (1,0) [0|255] ""  IMM

BO_ 2332108952 M2I_Byrack_SUMDATA8__08: 8 MBMU
 SG_ CRC_M2I_Byrack_IMM8_08 : 0|8@1+ (1,0) [0|255] ""  IMM
 SG_ M2I_Byrack_HVS_IMM8_08 : 8|16@1+ (0.1,0) [0|6553.5] "v"  IMM
 SG_ M2I_Byrack_Enable_IMM8_08 : 24|2@1+ (1,0) [0|3] ""  IMM
 SG_ M2I_Byrack_ReVeEnable_IMM8_08 : 26|2@1+ (1,0) [0|3] ""  IMM
 SG_ Reserved_08 : 28|4@1+ (1,0) [0|15] ""  IMM
 SG_ M2I_Byrack_IsPostTm_IMM8_08 : 32|8@1+ (0.01,0) [0|2.55] "s"  IMM
 SG_ M2I_Byrack_SysABStTm_IMM8_08 : 40|16@1+ (0.01,0) [0|655.35] "s"  IMM
 SG_ Reserved_08 : 56|8@1+ (1,0) [0|255] ""  IMM

BO_ 2332108953 M2I_Byrack_SUMDATA8__09: 8 MBMU
 SG_ CRC_M2I_Byrack_IMM8_09 : 0|8@1+ (1,0) [0|255] ""  IMM
 SG_ M2I_Byrack_HVS_IMM8_09 : 8|16@1+ (0.1,0) [0|6553.5] "v"  IMM
 SG_ M2I_Byrack_Enable_IMM8_09 : 24|2@1+ (1,0) [0|3] ""  IMM
 SG_ M2I_Byrack_ReVeEnable_IMM8_09 : 26|2@1+ (1,0) [0|3] ""  IMM
 SG_ Reserved_09 : 28|4@1+ (1,0) [0|15] ""  IMM
 SG_ M2I_Byrack_IsPostTm_IMM8_09 : 32|8@1+ (0.01,0) [0|2.55] "s"  IMM
 SG_ M2I_Byrack_SysABStTm_IMM8_09 : 40|16@1+ (0.01,0) [0|655.35] "s"  IMM
 SG_ Reserved_09 : 56|8@1+ (1,0) [0|255] ""  IMM

BO_ 2332108954 M2I_Byrack_SUMDATA8__10: 8 MBMU
 SG_ CRC_M2I_Byrack_IMM8_10 : 0|8@1+ (1,0) [0|255] ""  IMM
 SG_ M2I_Byrack_HVS_IMM8_10 : 8|16@1+ (0.1,0) [0|6553.5] "v"  IMM
 SG_ M2I_Byrack_Enable_IMM8_10 : 24|2@1+ (1,0) [0|3] ""  IMM
 SG_ M2I_Byrack_ReVeEnable_IMM8_10 : 26|2@1+ (1,0) [0|3] ""  IMM
 SG_ Reserved_10 : 28|4@1+ (1,0) [0|15] ""  IMM
 SG_ M2I_Byrack_IsPostTm_IMM8_10 : 32|8@1+ (0.01,0) [0|2.55] "s"  IMM
 SG_ M2I_Byrack_SysABStTm_IMM8_10 : 40|16@1+ (0.01,0) [0|655.35] "s"  IMM
 SG_ Reserved_10 : 56|8@1+ (1,0) [0|255] ""  IMM

BO_ 2332108955 M2I_Byrack_SUMDATA8__11: 8 MBMU
 SG_ CRC_M2I_Byrack_IMM8_11 : 0|8@1+ (1,0) [0|255] ""  IMM
 SG_ M2I_Byrack_HVS_IMM8_11 : 8|16@1+ (0.1,0) [0|6553.5] "v"  IMM
 SG_ M2I_Byrack_Enable_IMM8_11 : 24|2@1+ (1,0) [0|3] ""  IMM
 SG_ M2I_Byrack_ReVeEnable_IMM8_11 : 26|2@1+ (1,0) [0|3] ""  IMM
 SG_ Reserved_11 : 28|4@1+ (1,0) [0|15] ""  IMM
 SG_ M2I_Byrack_IsPostTm_IMM8_11 : 32|8@1+ (0.01,0) [0|2.55] "s"  IMM
 SG_ M2I_Byrack_SysABStTm_IMM8_11 : 40|16@1+ (0.01,0) [0|655.35] "s"  IMM
 SG_ Reserved_11 : 56|8@1+ (1,0) [0|255] ""  IMM

BO_ 2332108956 M2I_Byrack_SUMDATA8__12: 8 MBMU
 SG_ CRC_M2I_Byrack_IMM8_12 : 0|8@1+ (1,0) [0|255] ""  IMM
 SG_ M2I_Byrack_HVS_IMM8_12 : 8|16@1+ (0.1,0) [0|6553.5] "v"  IMM
 SG_ M2I_Byrack_Enable_IMM8_12 : 24|2@1+ (1,0) [0|3] ""  IMM
 SG_ M2I_Byrack_ReVeEnable_IMM8_12 : 26|2@1+ (1,0) [0|3] ""  IMM
 SG_ Reserved_12 : 28|4@1+ (1,0) [0|15] ""  IMM
 SG_ M2I_Byrack_IsPostTm_IMM8_12 : 32|8@1+ (0.01,0) [0|2.55] "s"  IMM
 SG_ M2I_Byrack_SysABStTm_IMM8_12 : 40|16@1+ (0.01,0) [0|655.35] "s"  IMM
 SG_ Reserved_12 : 56|8@1+ (1,0) [0|255] ""  IMM

BO_ 2332108957 M2I_Byrack_SUMDATA8__13: 8 MBMU
 SG_ CRC_M2I_Byrack_IMM8_13 : 0|8@1+ (1,0) [0|255] ""  IMM
 SG_ M2I_Byrack_HVS_IMM8_13 : 8|16@1+ (0.1,0) [0|6553.5] "v"  IMM
 SG_ M2I_Byrack_Enable_IMM8_13 : 24|2@1+ (1,0) [0|3] ""  IMM
 SG_ M2I_Byrack_ReVeEnable_IMM8_13 : 26|2@1+ (1,0) [0|3] ""  IMM
 SG_ Reserved_13 : 28|4@1+ (1,0) [0|15] ""  IMM
 SG_ M2I_Byrack_IsPostTm_IMM8_13 : 32|8@1+ (0.01,0) [0|2.55] "s"  IMM
 SG_ M2I_Byrack_SysABStTm_IMM8_13 : 40|16@1+ (0.01,0) [0|655.35] "s"  IMM
 SG_ Reserved_13 : 56|8@1+ (1,0) [0|255] ""  IMM

BO_ 2332108958 M2I_Byrack_SUMDATA8__14: 8 MBMU
 SG_ CRC_M2I_Byrack_IMM8_14 : 0|8@1+ (1,0) [0|255] ""  IMM
 SG_ M2I_Byrack_HVS_IMM8_14 : 8|16@1+ (0.1,0) [0|6553.5] "v"  IMM
 SG_ M2I_Byrack_Enable_IMM8_14 : 24|2@1+ (1,0) [0|3] ""  IMM
 SG_ M2I_Byrack_ReVeEnable_IMM8_14 : 26|2@1+ (1,0) [0|3] ""  IMM
 SG_ Reserved_14 : 28|4@1+ (1,0) [0|15] ""  IMM
 SG_ M2I_Byrack_IsPostTm_IMM8_14 : 32|8@1+ (0.01,0) [0|2.55] "s"  IMM
 SG_ M2I_Byrack_SysABStTm_IMM8_14 : 40|16@1+ (0.01,0) [0|655.35] "s"  IMM
 SG_ Reserved_14 : 56|8@1+ (1,0) [0|255] ""  IMM

BO_ 2332108959 M2I_Byrack_SUMDATA8__15: 8 MBMU
 SG_ CRC_M2I_Byrack_IMM8_15 : 0|8@1+ (1,0) [0|255] ""  IMM
 SG_ M2I_Byrack_HVS_IMM8_15 : 8|16@1+ (0.1,0) [0|6553.5] "v"  IMM
 SG_ M2I_Byrack_Enable_IMM8_15 : 24|2@1+ (1,0) [0|3] ""  IMM
 SG_ M2I_Byrack_ReVeEnable_IMM8_15 : 26|2@1+ (1,0) [0|3] ""  IMM
 SG_ Reserved_15 : 28|4@1+ (1,0) [0|15] ""  IMM
 SG_ M2I_Byrack_IsPostTm_IMM8_15 : 32|8@1+ (0.01,0) [0|2.55] "s"  IMM
 SG_ M2I_Byrack_SysABStTm_IMM8_15 : 40|16@1+ (0.01,0) [0|655.35] "s"  IMM
 SG_ Reserved_15 : 56|8@1+ (1,0) [0|255] ""  IMM

BO_ 2332108960 M2I_Byrack_SUMDATA8__16: 8 MBMU
 SG_ CRC_M2I_Byrack_IMM8_16 : 0|8@1+ (1,0) [0|255] ""  IMM
 SG_ M2I_Byrack_HVS_IMM8_16 : 8|16@1+ (0.1,0) [0|6553.5] "v"  IMM
 SG_ M2I_Byrack_Enable_IMM8_16 : 24|2@1+ (1,0) [0|3] ""  IMM
 SG_ M2I_Byrack_ReVeEnable_IMM8_16 : 26|2@1+ (1,0) [0|3] ""  IMM
 SG_ Reserved_16 : 28|4@1+ (1,0) [0|15] ""  IMM
 SG_ M2I_Byrack_IsPostTm_IMM8_16 : 32|8@1+ (0.01,0) [0|2.55] "s"  IMM
 SG_ M2I_Byrack_SysABStTm_IMM8_16 : 40|16@1+ (0.01,0) [0|655.35] "s"  IMM
 SG_ Reserved_16 : 56|8@1+ (1,0) [0|255] ""  IMM

BO_ 2332108961 M2I_Byrack_SUMDATA8__17: 8 MBMU
 SG_ CRC_M2I_Byrack_IMM8_17 : 0|8@1+ (1,0) [0|255] ""  IMM
 SG_ M2I_Byrack_HVS_IMM8_17 : 8|16@1+ (0.1,0) [0|6553.5] "v"  IMM
 SG_ M2I_Byrack_Enable_IMM8_17 : 24|2@1+ (1,0) [0|3] ""  IMM
 SG_ M2I_Byrack_ReVeEnable_IMM8_17 : 26|2@1+ (1,0) [0|3] ""  IMM
 SG_ Reserved_17 : 28|4@1+ (1,0) [0|15] ""  IMM
 SG_ M2I_Byrack_IsPostTm_IMM8_17 : 32|8@1+ (0.01,0) [0|2.55] "s"  IMM
 SG_ M2I_Byrack_SysABStTm_IMM8_17 : 40|16@1+ (0.01,0) [0|655.35] "s"  IMM
 SG_ Reserved_17 : 56|8@1+ (1,0) [0|255] ""  IMM

BO_ 2332108962 M2I_Byrack_SUMDATA8__18: 8 MBMU
 SG_ CRC_M2I_Byrack_IMM8_18 : 0|8@1+ (1,0) [0|255] ""  IMM
 SG_ M2I_Byrack_HVS_IMM8_18 : 8|16@1+ (0.1,0) [0|6553.5] "v"  IMM
 SG_ M2I_Byrack_Enable_IMM8_18 : 24|2@1+ (1,0) [0|3] ""  IMM
 SG_ M2I_Byrack_ReVeEnable_IMM8_18 : 26|2@1+ (1,0) [0|3] ""  IMM
 SG_ Reserved_18 : 28|4@1+ (1,0) [0|15] ""  IMM
 SG_ M2I_Byrack_IsPostTm_IMM8_18 : 32|8@1+ (0.01,0) [0|2.55] "s"  IMM
 SG_ M2I_Byrack_SysABStTm_IMM8_18 : 40|16@1+ (0.01,0) [0|655.35] "s"  IMM
 SG_ Reserved_18 : 56|8@1+ (1,0) [0|255] ""  IMM

BO_ 2332108963 M2I_Byrack_SUMDATA8__19: 8 MBMU
 SG_ CRC_M2I_Byrack_IMM8_19 : 0|8@1+ (1,0) [0|255] ""  IMM
 SG_ M2I_Byrack_HVS_IMM8_19 : 8|16@1+ (0.1,0) [0|6553.5] "v"  IMM
 SG_ M2I_Byrack_Enable_IMM8_19 : 24|2@1+ (1,0) [0|3] ""  IMM
 SG_ M2I_Byrack_ReVeEnable_IMM8_19 : 26|2@1+ (1,0) [0|3] ""  IMM
 SG_ Reserved_19 : 28|4@1+ (1,0) [0|15] ""  IMM
 SG_ M2I_Byrack_IsPostTm_IMM8_19 : 32|8@1+ (0.01,0) [0|2.55] "s"  IMM
 SG_ M2I_Byrack_SysABStTm_IMM8_19 : 40|16@1+ (0.01,0) [0|655.35] "s"  IMM
 SG_ Reserved_19 : 56|8@1+ (1,0) [0|255] ""  IMM

BO_ 2332108964 M2I_Byrack_SUMDATA8__20: 8 MBMU
 SG_ CRC_M2I_Byrack_IMM8_20 : 0|8@1+ (1,0) [0|255] ""  IMM
 SG_ M2I_Byrack_HVS_IMM8_20 : 8|16@1+ (0.1,0) [0|6553.5] "v"  IMM
 SG_ M2I_Byrack_Enable_IMM8_20 : 24|2@1+ (1,0) [0|3] ""  IMM
 SG_ M2I_Byrack_ReVeEnable_IMM8_20 : 26|2@1+ (1,0) [0|3] ""  IMM
 SG_ Reserved_20 : 28|4@1+ (1,0) [0|15] ""  IMM
 SG_ M2I_Byrack_IsPostTm_IMM8_20 : 32|8@1+ (0.01,0) [0|2.55] "s"  IMM
 SG_ M2I_Byrack_SysABStTm_IMM8_20 : 40|16@1+ (0.01,0) [0|655.35] "s"  IMM
 SG_ Reserved_20 : 56|8@1+ (1,0) [0|255] ""  IMM

BO_ 2332108965 M2I_Byrack_SUMDATA8__21: 8 MBMU
 SG_ CRC_M2I_Byrack_IMM8_21 : 0|8@1+ (1,0) [0|255] ""  IMM
 SG_ M2I_Byrack_HVS_IMM8_21 : 8|16@1+ (0.1,0) [0|6553.5] "v"  IMM
 SG_ M2I_Byrack_Enable_IMM8_21 : 24|2@1+ (1,0) [0|3] ""  IMM
 SG_ M2I_Byrack_ReVeEnable_IMM8_21 : 26|2@1+ (1,0) [0|3] ""  IMM
 SG_ Reserved_21 : 28|4@1+ (1,0) [0|15] ""  IMM
 SG_ M2I_Byrack_IsPostTm_IMM8_21 : 32|8@1+ (0.01,0) [0|2.55] "s"  IMM
 SG_ M2I_Byrack_SysABStTm_IMM8_21 : 40|16@1+ (0.01,0) [0|655.35] "s"  IMM
 SG_ Reserved_21 : 56|8@1+ (1,0) [0|255] ""  IMM

BO_ 2332108966 M2I_Byrack_SUMDATA8__22: 8 MBMU
 SG_ CRC_M2I_Byrack_IMM8_22 : 0|8@1+ (1,0) [0|255] ""  IMM
 SG_ M2I_Byrack_HVS_IMM8_22 : 8|16@1+ (0.1,0) [0|6553.5] "v"  IMM
 SG_ M2I_Byrack_Enable_IMM8_22 : 24|2@1+ (1,0) [0|3] ""  IMM
 SG_ M2I_Byrack_ReVeEnable_IMM8_22 : 26|2@1+ (1,0) [0|3] ""  IMM
 SG_ Reserved_22 : 28|4@1+ (1,0) [0|15] ""  IMM
 SG_ M2I_Byrack_IsPostTm_IMM8_22 : 32|8@1+ (0.01,0) [0|2.55] "s"  IMM
 SG_ M2I_Byrack_SysABStTm_IMM8_22 : 40|16@1+ (0.01,0) [0|655.35] "s"  IMM
 SG_ Reserved_22 : 56|8@1+ (1,0) [0|255] ""  IMM

BO_ 2332108967 M2I_Byrack_SUMDATA8__23: 8 MBMU
 SG_ CRC_M2I_Byrack_IMM8_23 : 0|8@1+ (1,0) [0|255] ""  IMM
 SG_ M2I_Byrack_HVS_IMM8_23 : 8|16@1+ (0.1,0) [0|6553.5] "v"  IMM
 SG_ M2I_Byrack_Enable_IMM8_23 : 24|2@1+ (1,0) [0|3] ""  IMM
 SG_ M2I_Byrack_ReVeEnable_IMM8_23 : 26|2@1+ (1,0) [0|3] ""  IMM
 SG_ Reserved_23 : 28|4@1+ (1,0) [0|15] ""  IMM
 SG_ M2I_Byrack_IsPostTm_IMM8_23 : 32|8@1+ (0.01,0) [0|2.55] "s"  IMM
 SG_ M2I_Byrack_SysABStTm_IMM8_23 : 40|16@1+ (0.01,0) [0|655.35] "s"  IMM
 SG_ Reserved_23 : 56|8@1+ (1,0) [0|255] ""  IMM

BO_ 2332108968 M2I_Byrack_SUMDATA8__24: 8 MBMU
 SG_ CRC_M2I_Byrack_IMM8_24 : 0|8@1+ (1,0) [0|255] ""  IMM
 SG_ M2I_Byrack_HVS_IMM8_24 : 8|16@1+ (0.1,0) [0|6553.5] "v"  IMM
 SG_ M2I_Byrack_Enable_IMM8_24 : 24|2@1+ (1,0) [0|3] ""  IMM
 SG_ M2I_Byrack_ReVeEnable_IMM8_24 : 26|2@1+ (1,0) [0|3] ""  IMM
 SG_ Reserved_24 : 28|4@1+ (1,0) [0|15] ""  IMM
 SG_ M2I_Byrack_IsPostTm_IMM8_24 : 32|8@1+ (0.01,0) [0|2.55] "s"  IMM
 SG_ M2I_Byrack_SysABStTm_IMM8_24 : 40|16@1+ (0.01,0) [0|655.35] "s"  IMM
 SG_ Reserved_24 : 56|8@1+ (1,0) [0|255] ""  IMM

BO_ 2332108969 M2I_Byrack_SUMDATA8__25: 8 MBMU
 SG_ CRC_M2I_Byrack_IMM8_25 : 0|8@1+ (1,0) [0|255] ""  IMM
 SG_ M2I_Byrack_HVS_IMM8_25 : 8|16@1+ (0.1,0) [0|6553.5] "v"  IMM
 SG_ M2I_Byrack_Enable_IMM8_25 : 24|2@1+ (1,0) [0|3] ""  IMM
 SG_ M2I_Byrack_ReVeEnable_IMM8_25 : 26|2@1+ (1,0) [0|3] ""  IMM
 SG_ Reserved_25 : 28|4@1+ (1,0) [0|15] ""  IMM
 SG_ M2I_Byrack_IsPostTm_IMM8_25 : 32|8@1+ (0.01,0) [0|2.55] "s"  IMM
 SG_ M2I_Byrack_SysABStTm_IMM8_25 : 40|16@1+ (0.01,0) [0|655.35] "s"  IMM
 SG_ Reserved_25 : 56|8@1+ (1,0) [0|255] ""  IMM

BO_ 2332108970 M2I_Byrack_SUMDATA8__26: 8 MBMU
 SG_ CRC_M2I_Byrack_IMM8_26 : 0|8@1+ (1,0) [0|255] ""  IMM
 SG_ M2I_Byrack_HVS_IMM8_26 : 8|16@1+ (0.1,0) [0|6553.5] "v"  IMM
 SG_ M2I_Byrack_Enable_IMM8_26 : 24|2@1+ (1,0) [0|3] ""  IMM
 SG_ M2I_Byrack_ReVeEnable_IMM8_26 : 26|2@1+ (1,0) [0|3] ""  IMM
 SG_ Reserved_26 : 28|4@1+ (1,0) [0|15] ""  IMM
 SG_ M2I_Byrack_IsPostTm_IMM8_26 : 32|8@1+ (0.01,0) [0|2.55] "s"  IMM
 SG_ M2I_Byrack_SysABStTm_IMM8_26 : 40|16@1+ (0.01,0) [0|655.35] "s"  IMM
 SG_ Reserved_26 : 56|8@1+ (1,0) [0|255] ""  IMM

BO_ 2332108971 M2I_Byrack_SUMDATA8__27: 8 MBMU
 SG_ CRC_M2I_Byrack_IMM8_27 : 0|8@1+ (1,0) [0|255] ""  IMM
 SG_ M2I_Byrack_HVS_IMM8_27 : 8|16@1+ (0.1,0) [0|6553.5] "v"  IMM
 SG_ M2I_Byrack_Enable_IMM8_27 : 24|2@1+ (1,0) [0|3] ""  IMM
 SG_ M2I_Byrack_ReVeEnable_IMM8_27 : 26|2@1+ (1,0) [0|3] ""  IMM
 SG_ Reserved_27 : 28|4@1+ (1,0) [0|15] ""  IMM
 SG_ M2I_Byrack_IsPostTm_IMM8_27 : 32|8@1+ (0.01,0) [0|2.55] "s"  IMM
 SG_ M2I_Byrack_SysABStTm_IMM8_27 : 40|16@1+ (0.01,0) [0|655.35] "s"  IMM
 SG_ Reserved_27 : 56|8@1+ (1,0) [0|255] ""  IMM

BO_ 2332108972 M2I_Byrack_SUMDATA8__28: 8 MBMU
 SG_ CRC_M2I_Byrack_IMM8_28 : 0|8@1+ (1,0) [0|255] ""  IMM
 SG_ M2I_Byrack_HVS_IMM8_28 : 8|16@1+ (0.1,0) [0|6553.5] "v"  IMM
 SG_ M2I_Byrack_Enable_IMM8_28 : 24|2@1+ (1,0) [0|3] ""  IMM
 SG_ M2I_Byrack_ReVeEnable_IMM8_28 : 26|2@1+ (1,0) [0|3] ""  IMM
 SG_ Reserved_28 : 28|4@1+ (1,0) [0|15] ""  IMM
 SG_ M2I_Byrack_IsPostTm_IMM8_28 : 32|8@1+ (0.01,0) [0|2.55] "s"  IMM
 SG_ M2I_Byrack_SysABStTm_IMM8_28 : 40|16@1+ (0.01,0) [0|655.35] "s"  IMM
 SG_ Reserved_28 : 56|8@1+ (1,0) [0|255] ""  IMM

BO_ 2332108973 M2I_Byrack_SUMDATA8__29: 8 MBMU
 SG_ CRC_M2I_Byrack_IMM8_29 : 0|8@1+ (1,0) [0|255] ""  IMM
 SG_ M2I_Byrack_HVS_IMM8_29 : 8|16@1+ (0.1,0) [0|6553.5] "v"  IMM
 SG_ M2I_Byrack_Enable_IMM8_29 : 24|2@1+ (1,0) [0|3] ""  IMM
 SG_ M2I_Byrack_ReVeEnable_IMM8_29 : 26|2@1+ (1,0) [0|3] ""  IMM
 SG_ Reserved_29 : 28|4@1+ (1,0) [0|15] ""  IMM
 SG_ M2I_Byrack_IsPostTm_IMM8_29 : 32|8@1+ (0.01,0) [0|2.55] "s"  IMM
 SG_ M2I_Byrack_SysABStTm_IMM8_29 : 40|16@1+ (0.01,0) [0|655.35] "s"  IMM
 SG_ Reserved_29 : 56|8@1+ (1,0) [0|255] ""  IMM

BO_ 2332108974 M2I_Byrack_SUMDATA8__30: 8 MBMU
 SG_ CRC_M2I_Byrack_IMM8_30 : 0|8@1+ (1,0) [0|255] ""  IMM
 SG_ M2I_Byrack_HVS_IMM8_30 : 8|16@1+ (0.1,0) [0|6553.5] "v"  IMM
 SG_ M2I_Byrack_Enable_IMM8_30 : 24|2@1+ (1,0) [0|3] ""  IMM
 SG_ M2I_Byrack_ReVeEnable_IMM8_30 : 26|2@1+ (1,0) [0|3] ""  IMM
 SG_ Reserved_30 : 28|4@1+ (1,0) [0|15] ""  IMM
 SG_ M2I_Byrack_IsPostTm_IMM8_30 : 32|8@1+ (0.01,0) [0|2.55] "s"  IMM
 SG_ M2I_Byrack_SysABStTm_IMM8_30 : 40|16@1+ (0.01,0) [0|655.35] "s"  IMM
 SG_ Reserved_30 : 56|8@1+ (1,0) [0|255] ""  IMM

BO_ 2332108975 M2I_Byrack_SUMDATA8__31: 8 MBMU
 SG_ CRC_M2I_Byrack_IMM8_31 : 0|8@1+ (1,0) [0|255] ""  IMM
 SG_ M2I_Byrack_HVS_IMM8_31 : 8|16@1+ (0.1,0) [0|6553.5] "v"  IMM
 SG_ M2I_Byrack_Enable_IMM8_31 : 24|2@1+ (1,0) [0|3] ""  IMM
 SG_ M2I_Byrack_ReVeEnable_IMM8_31 : 26|2@1+ (1,0) [0|3] ""  IMM
 SG_ Reserved_31 : 28|4@1+ (1,0) [0|15] ""  IMM
 SG_ M2I_Byrack_IsPostTm_IMM8_31 : 32|8@1+ (0.01,0) [0|2.55] "s"  IMM
 SG_ M2I_Byrack_SysABStTm_IMM8_31 : 40|16@1+ (0.01,0) [0|655.35] "s"  IMM
 SG_ Reserved_31 : 56|8@1+ (1,0) [0|255] ""  IMM

BO_ 2332109201 M2I_Byrack_SUMDATA9__01: 8 MBMU
 SG_ CRC_M2I_Byrack_IMM9_01 : 0|8@1+ (1,0) [0|255] ""  IMM
 SG_ M2I_Byrack_HVS_IMM9_01 : 8|16@1+ (0.1,0) [0|6553.5] "v"  IMM
 SG_ M2I_Byrack_Enable_IMM9_01 : 24|2@1+ (1,0) [0|3] ""  IMM
 SG_ M2I_Byrack_ReVeEnable_IMM9_01 : 26|2@1+ (1,0) [0|3] ""  IMM
 SG_ Reserved_01 : 28|4@1+ (1,0) [0|15] ""  IMM
 SG_ M2I_Byrack_IsPostTm_IMM9_01 : 32|8@1+ (0.01,0) [0|2.55] "s"  IMM
 SG_ M2I_Byrack_SysABStTm_IMM9_01 : 40|16@1+ (0.01,0) [0|655.35] "s"  IMM
 SG_ Reserved_01 : 56|8@1+ (1,0) [0|255] ""  IMM

BO_ 2332109202 M2I_Byrack_SUMDATA9__02: 8 MBMU
 SG_ CRC_M2I_Byrack_IMM9_02 : 0|8@1+ (1,0) [0|255] ""  IMM
 SG_ M2I_Byrack_HVS_IMM9_02 : 8|16@1+ (0.1,0) [0|6553.5] "v"  IMM
 SG_ M2I_Byrack_Enable_IMM9_02 : 24|2@1+ (1,0) [0|3] ""  IMM
 SG_ M2I_Byrack_ReVeEnable_IMM9_02 : 26|2@1+ (1,0) [0|3] ""  IMM
 SG_ Reserved_02 : 28|4@1+ (1,0) [0|15] ""  IMM
 SG_ M2I_Byrack_IsPostTm_IMM9_02 : 32|8@1+ (0.01,0) [0|2.55] "s"  IMM
 SG_ M2I_Byrack_SysABStTm_IMM9_02 : 40|16@1+ (0.01,0) [0|655.35] "s"  IMM
 SG_ Reserved_02 : 56|8@1+ (1,0) [0|255] ""  IMM

BO_ 2332109203 M2I_Byrack_SUMDATA9__03: 8 MBMU
 SG_ CRC_M2I_Byrack_IMM9_03 : 0|8@1+ (1,0) [0|255] ""  IMM
 SG_ M2I_Byrack_HVS_IMM9_03 : 8|16@1+ (0.1,0) [0|6553.5] "v"  IMM
 SG_ M2I_Byrack_Enable_IMM9_03 : 24|2@1+ (1,0) [0|3] ""  IMM
 SG_ M2I_Byrack_ReVeEnable_IMM9_03 : 26|2@1+ (1,0) [0|3] ""  IMM
 SG_ Reserved_03 : 28|4@1+ (1,0) [0|15] ""  IMM
 SG_ M2I_Byrack_IsPostTm_IMM9_03 : 32|8@1+ (0.01,0) [0|2.55] "s"  IMM
 SG_ M2I_Byrack_SysABStTm_IMM9_03 : 40|16@1+ (0.01,0) [0|655.35] "s"  IMM
 SG_ Reserved_03 : 56|8@1+ (1,0) [0|255] ""  IMM

BO_ 2332109204 M2I_Byrack_SUMDATA9__04: 8 MBMU
 SG_ CRC_M2I_Byrack_IMM9_04 : 0|8@1+ (1,0) [0|255] ""  IMM
 SG_ M2I_Byrack_HVS_IMM9_04 : 8|16@1+ (0.1,0) [0|6553.5] "v"  IMM
 SG_ M2I_Byrack_Enable_IMM9_04 : 24|2@1+ (1,0) [0|3] ""  IMM
 SG_ M2I_Byrack_ReVeEnable_IMM9_04 : 26|2@1+ (1,0) [0|3] ""  IMM
 SG_ Reserved_04 : 28|4@1+ (1,0) [0|15] ""  IMM
 SG_ M2I_Byrack_IsPostTm_IMM9_04 : 32|8@1+ (0.01,0) [0|2.55] "s"  IMM
 SG_ M2I_Byrack_SysABStTm_IMM9_04 : 40|16@1+ (0.01,0) [0|655.35] "s"  IMM
 SG_ Reserved_04 : 56|8@1+ (1,0) [0|255] ""  IMM

BO_ 2332109205 M2I_Byrack_SUMDATA9__05: 8 MBMU
 SG_ CRC_M2I_Byrack_IMM9_05 : 0|8@1+ (1,0) [0|255] ""  IMM
 SG_ M2I_Byrack_HVS_IMM9_05 : 8|16@1+ (0.1,0) [0|6553.5] "v"  IMM
 SG_ M2I_Byrack_Enable_IMM9_05 : 24|2@1+ (1,0) [0|3] ""  IMM
 SG_ M2I_Byrack_ReVeEnable_IMM9_05 : 26|2@1+ (1,0) [0|3] ""  IMM
 SG_ Reserved_05 : 28|4@1+ (1,0) [0|15] ""  IMM
 SG_ M2I_Byrack_IsPostTm_IMM9_05 : 32|8@1+ (0.01,0) [0|2.55] "s"  IMM
 SG_ M2I_Byrack_SysABStTm_IMM9_05 : 40|16@1+ (0.01,0) [0|655.35] "s"  IMM
 SG_ Reserved_05 : 56|8@1+ (1,0) [0|255] ""  IMM

BO_ 2332109206 M2I_Byrack_SUMDATA9__06: 8 MBMU
 SG_ CRC_M2I_Byrack_IMM9_06 : 0|8@1+ (1,0) [0|255] ""  IMM
 SG_ M2I_Byrack_HVS_IMM9_06 : 8|16@1+ (0.1,0) [0|6553.5] "v"  IMM
 SG_ M2I_Byrack_Enable_IMM9_06 : 24|2@1+ (1,0) [0|3] ""  IMM
 SG_ M2I_Byrack_ReVeEnable_IMM9_06 : 26|2@1+ (1,0) [0|3] ""  IMM
 SG_ Reserved_06 : 28|4@1+ (1,0) [0|15] ""  IMM
 SG_ M2I_Byrack_IsPostTm_IMM9_06 : 32|8@1+ (0.01,0) [0|2.55] "s"  IMM
 SG_ M2I_Byrack_SysABStTm_IMM9_06 : 40|16@1+ (0.01,0) [0|655.35] "s"  IMM
 SG_ Reserved_06 : 56|8@1+ (1,0) [0|255] ""  IMM

BO_ 2332109207 M2I_Byrack_SUMDATA9__07: 8 MBMU
 SG_ CRC_M2I_Byrack_IMM9_07 : 0|8@1+ (1,0) [0|255] ""  IMM
 SG_ M2I_Byrack_HVS_IMM9_07 : 8|16@1+ (0.1,0) [0|6553.5] "v"  IMM
 SG_ M2I_Byrack_Enable_IMM9_07 : 24|2@1+ (1,0) [0|3] ""  IMM
 SG_ M2I_Byrack_ReVeEnable_IMM9_07 : 26|2@1+ (1,0) [0|3] ""  IMM
 SG_ Reserved_07 : 28|4@1+ (1,0) [0|15] ""  IMM
 SG_ M2I_Byrack_IsPostTm_IMM9_07 : 32|8@1+ (0.01,0) [0|2.55] "s"  IMM
 SG_ M2I_Byrack_SysABStTm_IMM9_07 : 40|16@1+ (0.01,0) [0|655.35] "s"  IMM
 SG_ Reserved_07 : 56|8@1+ (1,0) [0|255] ""  IMM

BO_ 2332109208 M2I_Byrack_SUMDATA9__08: 8 MBMU
 SG_ CRC_M2I_Byrack_IMM9_08 : 0|8@1+ (1,0) [0|255] ""  IMM
 SG_ M2I_Byrack_HVS_IMM9_08 : 8|16@1+ (0.1,0) [0|6553.5] "v"  IMM
 SG_ M2I_Byrack_Enable_IMM9_08 : 24|2@1+ (1,0) [0|3] ""  IMM
 SG_ M2I_Byrack_ReVeEnable_IMM9_08 : 26|2@1+ (1,0) [0|3] ""  IMM
 SG_ Reserved_08 : 28|4@1+ (1,0) [0|15] ""  IMM
 SG_ M2I_Byrack_IsPostTm_IMM9_08 : 32|8@1+ (0.01,0) [0|2.55] "s"  IMM
 SG_ M2I_Byrack_SysABStTm_IMM9_08 : 40|16@1+ (0.01,0) [0|655.35] "s"  IMM
 SG_ Reserved_08 : 56|8@1+ (1,0) [0|255] ""  IMM

BO_ 2332109209 M2I_Byrack_SUMDATA9__09: 8 MBMU
 SG_ CRC_M2I_Byrack_IMM9_09 : 0|8@1+ (1,0) [0|255] ""  IMM
 SG_ M2I_Byrack_HVS_IMM9_09 : 8|16@1+ (0.1,0) [0|6553.5] "v"  IMM
 SG_ M2I_Byrack_Enable_IMM9_09 : 24|2@1+ (1,0) [0|3] ""  IMM
 SG_ M2I_Byrack_ReVeEnable_IMM9_09 : 26|2@1+ (1,0) [0|3] ""  IMM
 SG_ Reserved_09 : 28|4@1+ (1,0) [0|15] ""  IMM
 SG_ M2I_Byrack_IsPostTm_IMM9_09 : 32|8@1+ (0.01,0) [0|2.55] "s"  IMM
 SG_ M2I_Byrack_SysABStTm_IMM9_09 : 40|16@1+ (0.01,0) [0|655.35] "s"  IMM
 SG_ Reserved_09 : 56|8@1+ (1,0) [0|255] ""  IMM

BO_ 2332109210 M2I_Byrack_SUMDATA9__10: 8 MBMU
 SG_ CRC_M2I_Byrack_IMM9_10 : 0|8@1+ (1,0) [0|255] ""  IMM
 SG_ M2I_Byrack_HVS_IMM9_10 : 8|16@1+ (0.1,0) [0|6553.5] "v"  IMM
 SG_ M2I_Byrack_Enable_IMM9_10 : 24|2@1+ (1,0) [0|3] ""  IMM
 SG_ M2I_Byrack_ReVeEnable_IMM9_10 : 26|2@1+ (1,0) [0|3] ""  IMM
 SG_ Reserved_10 : 28|4@1+ (1,0) [0|15] ""  IMM
 SG_ M2I_Byrack_IsPostTm_IMM9_10 : 32|8@1+ (0.01,0) [0|2.55] "s"  IMM
 SG_ M2I_Byrack_SysABStTm_IMM9_10 : 40|16@1+ (0.01,0) [0|655.35] "s"  IMM
 SG_ Reserved_10 : 56|8@1+ (1,0) [0|255] ""  IMM

BO_ 2332109211 M2I_Byrack_SUMDATA9__11: 8 MBMU
 SG_ CRC_M2I_Byrack_IMM9_11 : 0|8@1+ (1,0) [0|255] ""  IMM
 SG_ M2I_Byrack_HVS_IMM9_11 : 8|16@1+ (0.1,0) [0|6553.5] "v"  IMM
 SG_ M2I_Byrack_Enable_IMM9_11 : 24|2@1+ (1,0) [0|3] ""  IMM
 SG_ M2I_Byrack_ReVeEnable_IMM9_11 : 26|2@1+ (1,0) [0|3] ""  IMM
 SG_ Reserved_11 : 28|4@1+ (1,0) [0|15] ""  IMM
 SG_ M2I_Byrack_IsPostTm_IMM9_11 : 32|8@1+ (0.01,0) [0|2.55] "s"  IMM
 SG_ M2I_Byrack_SysABStTm_IMM9_11 : 40|16@1+ (0.01,0) [0|655.35] "s"  IMM
 SG_ Reserved_11 : 56|8@1+ (1,0) [0|255] ""  IMM

BO_ 2332109212 M2I_Byrack_SUMDATA9__12: 8 MBMU
 SG_ CRC_M2I_Byrack_IMM9_12 : 0|8@1+ (1,0) [0|255] ""  IMM
 SG_ M2I_Byrack_HVS_IMM9_12 : 8|16@1+ (0.1,0) [0|6553.5] "v"  IMM
 SG_ M2I_Byrack_Enable_IMM9_12 : 24|2@1+ (1,0) [0|3] ""  IMM
 SG_ M2I_Byrack_ReVeEnable_IMM9_12 : 26|2@1+ (1,0) [0|3] ""  IMM
 SG_ Reserved_12 : 28|4@1+ (1,0) [0|15] ""  IMM
 SG_ M2I_Byrack_IsPostTm_IMM9_12 : 32|8@1+ (0.01,0) [0|2.55] "s"  IMM
 SG_ M2I_Byrack_SysABStTm_IMM9_12 : 40|16@1+ (0.01,0) [0|655.35] "s"  IMM
 SG_ Reserved_12 : 56|8@1+ (1,0) [0|255] ""  IMM

BO_ 2332109213 M2I_Byrack_SUMDATA9__13: 8 MBMU
 SG_ CRC_M2I_Byrack_IMM9_13 : 0|8@1+ (1,0) [0|255] ""  IMM
 SG_ M2I_Byrack_HVS_IMM9_13 : 8|16@1+ (0.1,0) [0|6553.5] "v"  IMM
 SG_ M2I_Byrack_Enable_IMM9_13 : 24|2@1+ (1,0) [0|3] ""  IMM
 SG_ M2I_Byrack_ReVeEnable_IMM9_13 : 26|2@1+ (1,0) [0|3] ""  IMM
 SG_ Reserved_13 : 28|4@1+ (1,0) [0|15] ""  IMM
 SG_ M2I_Byrack_IsPostTm_IMM9_13 : 32|8@1+ (0.01,0) [0|2.55] "s"  IMM
 SG_ M2I_Byrack_SysABStTm_IMM9_13 : 40|16@1+ (0.01,0) [0|655.35] "s"  IMM
 SG_ Reserved_13 : 56|8@1+ (1,0) [0|255] ""  IMM

BO_ 2332109214 M2I_Byrack_SUMDATA9__14: 8 MBMU
 SG_ CRC_M2I_Byrack_IMM9_14 : 0|8@1+ (1,0) [0|255] ""  IMM
 SG_ M2I_Byrack_HVS_IMM9_14 : 8|16@1+ (0.1,0) [0|6553.5] "v"  IMM
 SG_ M2I_Byrack_Enable_IMM9_14 : 24|2@1+ (1,0) [0|3] ""  IMM
 SG_ M2I_Byrack_ReVeEnable_IMM9_14 : 26|2@1+ (1,0) [0|3] ""  IMM
 SG_ Reserved_14 : 28|4@1+ (1,0) [0|15] ""  IMM
 SG_ M2I_Byrack_IsPostTm_IMM9_14 : 32|8@1+ (0.01,0) [0|2.55] "s"  IMM
 SG_ M2I_Byrack_SysABStTm_IMM9_14 : 40|16@1+ (0.01,0) [0|655.35] "s"  IMM
 SG_ Reserved_14 : 56|8@1+ (1,0) [0|255] ""  IMM

BO_ 2332109215 M2I_Byrack_SUMDATA9__15: 8 MBMU
 SG_ CRC_M2I_Byrack_IMM9_15 : 0|8@1+ (1,0) [0|255] ""  IMM
 SG_ M2I_Byrack_HVS_IMM9_15 : 8|16@1+ (0.1,0) [0|6553.5] "v"  IMM
 SG_ M2I_Byrack_Enable_IMM9_15 : 24|2@1+ (1,0) [0|3] ""  IMM
 SG_ M2I_Byrack_ReVeEnable_IMM9_15 : 26|2@1+ (1,0) [0|3] ""  IMM
 SG_ Reserved_15 : 28|4@1+ (1,0) [0|15] ""  IMM
 SG_ M2I_Byrack_IsPostTm_IMM9_15 : 32|8@1+ (0.01,0) [0|2.55] "s"  IMM
 SG_ M2I_Byrack_SysABStTm_IMM9_15 : 40|16@1+ (0.01,0) [0|655.35] "s"  IMM
 SG_ Reserved_15 : 56|8@1+ (1,0) [0|255] ""  IMM

BO_ 2332109216 M2I_Byrack_SUMDATA9__16: 8 MBMU
 SG_ CRC_M2I_Byrack_IMM9_16 : 0|8@1+ (1,0) [0|255] ""  IMM
 SG_ M2I_Byrack_HVS_IMM9_16 : 8|16@1+ (0.1,0) [0|6553.5] "v"  IMM
 SG_ M2I_Byrack_Enable_IMM9_16 : 24|2@1+ (1,0) [0|3] ""  IMM
 SG_ M2I_Byrack_ReVeEnable_IMM9_16 : 26|2@1+ (1,0) [0|3] ""  IMM
 SG_ Reserved_16 : 28|4@1+ (1,0) [0|15] ""  IMM
 SG_ M2I_Byrack_IsPostTm_IMM9_16 : 32|8@1+ (0.01,0) [0|2.55] "s"  IMM
 SG_ M2I_Byrack_SysABStTm_IMM9_16 : 40|16@1+ (0.01,0) [0|655.35] "s"  IMM
 SG_ Reserved_16 : 56|8@1+ (1,0) [0|255] ""  IMM

BO_ 2332109217 M2I_Byrack_SUMDATA9__17: 8 MBMU
 SG_ CRC_M2I_Byrack_IMM9_17 : 0|8@1+ (1,0) [0|255] ""  IMM
 SG_ M2I_Byrack_HVS_IMM9_17 : 8|16@1+ (0.1,0) [0|6553.5] "v"  IMM
 SG_ M2I_Byrack_Enable_IMM9_17 : 24|2@1+ (1,0) [0|3] ""  IMM
 SG_ M2I_Byrack_ReVeEnable_IMM9_17 : 26|2@1+ (1,0) [0|3] ""  IMM
 SG_ Reserved_17 : 28|4@1+ (1,0) [0|15] ""  IMM
 SG_ M2I_Byrack_IsPostTm_IMM9_17 : 32|8@1+ (0.01,0) [0|2.55] "s"  IMM
 SG_ M2I_Byrack_SysABStTm_IMM9_17 : 40|16@1+ (0.01,0) [0|655.35] "s"  IMM
 SG_ Reserved_17 : 56|8@1+ (1,0) [0|255] ""  IMM

BO_ 2332109218 M2I_Byrack_SUMDATA9__18: 8 MBMU
 SG_ CRC_M2I_Byrack_IMM9_18 : 0|8@1+ (1,0) [0|255] ""  IMM
 SG_ M2I_Byrack_HVS_IMM9_18 : 8|16@1+ (0.1,0) [0|6553.5] "v"  IMM
 SG_ M2I_Byrack_Enable_IMM9_18 : 24|2@1+ (1,0) [0|3] ""  IMM
 SG_ M2I_Byrack_ReVeEnable_IMM9_18 : 26|2@1+ (1,0) [0|3] ""  IMM
 SG_ Reserved_18 : 28|4@1+ (1,0) [0|15] ""  IMM
 SG_ M2I_Byrack_IsPostTm_IMM9_18 : 32|8@1+ (0.01,0) [0|2.55] "s"  IMM
 SG_ M2I_Byrack_SysABStTm_IMM9_18 : 40|16@1+ (0.01,0) [0|655.35] "s"  IMM
 SG_ Reserved_18 : 56|8@1+ (1,0) [0|255] ""  IMM

BO_ 2332109219 M2I_Byrack_SUMDATA9__19: 8 MBMU
 SG_ CRC_M2I_Byrack_IMM9_19 : 0|8@1+ (1,0) [0|255] ""  IMM
 SG_ M2I_Byrack_HVS_IMM9_19 : 8|16@1+ (0.1,0) [0|6553.5] "v"  IMM
 SG_ M2I_Byrack_Enable_IMM9_19 : 24|2@1+ (1,0) [0|3] ""  IMM
 SG_ M2I_Byrack_ReVeEnable_IMM9_19 : 26|2@1+ (1,0) [0|3] ""  IMM
 SG_ Reserved_19 : 28|4@1+ (1,0) [0|15] ""  IMM
 SG_ M2I_Byrack_IsPostTm_IMM9_19 : 32|8@1+ (0.01,0) [0|2.55] "s"  IMM
 SG_ M2I_Byrack_SysABStTm_IMM9_19 : 40|16@1+ (0.01,0) [0|655.35] "s"  IMM
 SG_ Reserved_19 : 56|8@1+ (1,0) [0|255] ""  IMM

BO_ 2332109220 M2I_Byrack_SUMDATA9__20: 8 MBMU
 SG_ CRC_M2I_Byrack_IMM9_20 : 0|8@1+ (1,0) [0|255] ""  IMM
 SG_ M2I_Byrack_HVS_IMM9_20 : 8|16@1+ (0.1,0) [0|6553.5] "v"  IMM
 SG_ M2I_Byrack_Enable_IMM9_20 : 24|2@1+ (1,0) [0|3] ""  IMM
 SG_ M2I_Byrack_ReVeEnable_IMM9_20 : 26|2@1+ (1,0) [0|3] ""  IMM
 SG_ Reserved_20 : 28|4@1+ (1,0) [0|15] ""  IMM
 SG_ M2I_Byrack_IsPostTm_IMM9_20 : 32|8@1+ (0.01,0) [0|2.55] "s"  IMM
 SG_ M2I_Byrack_SysABStTm_IMM9_20 : 40|16@1+ (0.01,0) [0|655.35] "s"  IMM
 SG_ Reserved_20 : 56|8@1+ (1,0) [0|255] ""  IMM

BO_ 2332109221 M2I_Byrack_SUMDATA9__21: 8 MBMU
 SG_ CRC_M2I_Byrack_IMM9_21 : 0|8@1+ (1,0) [0|255] ""  IMM
 SG_ M2I_Byrack_HVS_IMM9_21 : 8|16@1+ (0.1,0) [0|6553.5] "v"  IMM
 SG_ M2I_Byrack_Enable_IMM9_21 : 24|2@1+ (1,0) [0|3] ""  IMM
 SG_ M2I_Byrack_ReVeEnable_IMM9_21 : 26|2@1+ (1,0) [0|3] ""  IMM
 SG_ Reserved_21 : 28|4@1+ (1,0) [0|15] ""  IMM
 SG_ M2I_Byrack_IsPostTm_IMM9_21 : 32|8@1+ (0.01,0) [0|2.55] "s"  IMM
 SG_ M2I_Byrack_SysABStTm_IMM9_21 : 40|16@1+ (0.01,0) [0|655.35] "s"  IMM
 SG_ Reserved_21 : 56|8@1+ (1,0) [0|255] ""  IMM

BO_ 2332109222 M2I_Byrack_SUMDATA9__22: 8 MBMU
 SG_ CRC_M2I_Byrack_IMM9_22 : 0|8@1+ (1,0) [0|255] ""  IMM
 SG_ M2I_Byrack_HVS_IMM9_22 : 8|16@1+ (0.1,0) [0|6553.5] "v"  IMM
 SG_ M2I_Byrack_Enable_IMM9_22 : 24|2@1+ (1,0) [0|3] ""  IMM
 SG_ M2I_Byrack_ReVeEnable_IMM9_22 : 26|2@1+ (1,0) [0|3] ""  IMM
 SG_ Reserved_22 : 28|4@1+ (1,0) [0|15] ""  IMM
 SG_ M2I_Byrack_IsPostTm_IMM9_22 : 32|8@1+ (0.01,0) [0|2.55] "s"  IMM
 SG_ M2I_Byrack_SysABStTm_IMM9_22 : 40|16@1+ (0.01,0) [0|655.35] "s"  IMM
 SG_ Reserved_22 : 56|8@1+ (1,0) [0|255] ""  IMM

BO_ 2332109223 M2I_Byrack_SUMDATA9__23: 8 MBMU
 SG_ CRC_M2I_Byrack_IMM9_23 : 0|8@1+ (1,0) [0|255] ""  IMM
 SG_ M2I_Byrack_HVS_IMM9_23 : 8|16@1+ (0.1,0) [0|6553.5] "v"  IMM
 SG_ M2I_Byrack_Enable_IMM9_23 : 24|2@1+ (1,0) [0|3] ""  IMM
 SG_ M2I_Byrack_ReVeEnable_IMM9_23 : 26|2@1+ (1,0) [0|3] ""  IMM
 SG_ Reserved_23 : 28|4@1+ (1,0) [0|15] ""  IMM
 SG_ M2I_Byrack_IsPostTm_IMM9_23 : 32|8@1+ (0.01,0) [0|2.55] "s"  IMM
 SG_ M2I_Byrack_SysABStTm_IMM9_23 : 40|16@1+ (0.01,0) [0|655.35] "s"  IMM
 SG_ Reserved_23 : 56|8@1+ (1,0) [0|255] ""  IMM

BO_ 2332109224 M2I_Byrack_SUMDATA9__24: 8 MBMU
 SG_ CRC_M2I_Byrack_IMM9_24 : 0|8@1+ (1,0) [0|255] ""  IMM
 SG_ M2I_Byrack_HVS_IMM9_24 : 8|16@1+ (0.1,0) [0|6553.5] "v"  IMM
 SG_ M2I_Byrack_Enable_IMM9_24 : 24|2@1+ (1,0) [0|3] ""  IMM
 SG_ M2I_Byrack_ReVeEnable_IMM9_24 : 26|2@1+ (1,0) [0|3] ""  IMM
 SG_ Reserved_24 : 28|4@1+ (1,0) [0|15] ""  IMM
 SG_ M2I_Byrack_IsPostTm_IMM9_24 : 32|8@1+ (0.01,0) [0|2.55] "s"  IMM
 SG_ M2I_Byrack_SysABStTm_IMM9_24 : 40|16@1+ (0.01,0) [0|655.35] "s"  IMM
 SG_ Reserved_24 : 56|8@1+ (1,0) [0|255] ""  IMM

BO_ 2332109225 M2I_Byrack_SUMDATA9__25: 8 MBMU
 SG_ CRC_M2I_Byrack_IMM9_25 : 0|8@1+ (1,0) [0|255] ""  IMM
 SG_ M2I_Byrack_HVS_IMM9_25 : 8|16@1+ (0.1,0) [0|6553.5] "v"  IMM
 SG_ M2I_Byrack_Enable_IMM9_25 : 24|2@1+ (1,0) [0|3] ""  IMM
 SG_ M2I_Byrack_ReVeEnable_IMM9_25 : 26|2@1+ (1,0) [0|3] ""  IMM
 SG_ Reserved_25 : 28|4@1+ (1,0) [0|15] ""  IMM
 SG_ M2I_Byrack_IsPostTm_IMM9_25 : 32|8@1+ (0.01,0) [0|2.55] "s"  IMM
 SG_ M2I_Byrack_SysABStTm_IMM9_25 : 40|16@1+ (0.01,0) [0|655.35] "s"  IMM
 SG_ Reserved_25 : 56|8@1+ (1,0) [0|255] ""  IMM

BO_ 2332109226 M2I_Byrack_SUMDATA9__26: 8 MBMU
 SG_ CRC_M2I_Byrack_IMM9_26 : 0|8@1+ (1,0) [0|255] ""  IMM
 SG_ M2I_Byrack_HVS_IMM9_26 : 8|16@1+ (0.1,0) [0|6553.5] "v"  IMM
 SG_ M2I_Byrack_Enable_IMM9_26 : 24|2@1+ (1,0) [0|3] ""  IMM
 SG_ M2I_Byrack_ReVeEnable_IMM9_26 : 26|2@1+ (1,0) [0|3] ""  IMM
 SG_ Reserved_26 : 28|4@1+ (1,0) [0|15] ""  IMM
 SG_ M2I_Byrack_IsPostTm_IMM9_26 : 32|8@1+ (0.01,0) [0|2.55] "s"  IMM
 SG_ M2I_Byrack_SysABStTm_IMM9_26 : 40|16@1+ (0.01,0) [0|655.35] "s"  IMM
 SG_ Reserved_26 : 56|8@1+ (1,0) [0|255] ""  IMM

BO_ 2332109227 M2I_Byrack_SUMDATA9__27: 8 MBMU
 SG_ CRC_M2I_Byrack_IMM9_27 : 0|8@1+ (1,0) [0|255] ""  IMM
 SG_ M2I_Byrack_HVS_IMM9_27 : 8|16@1+ (0.1,0) [0|6553.5] "v"  IMM
 SG_ M2I_Byrack_Enable_IMM9_27 : 24|2@1+ (1,0) [0|3] ""  IMM
 SG_ M2I_Byrack_ReVeEnable_IMM9_27 : 26|2@1+ (1,0) [0|3] ""  IMM
 SG_ Reserved_27 : 28|4@1+ (1,0) [0|15] ""  IMM
 SG_ M2I_Byrack_IsPostTm_IMM9_27 : 32|8@1+ (0.01,0) [0|2.55] "s"  IMM
 SG_ M2I_Byrack_SysABStTm_IMM9_27 : 40|16@1+ (0.01,0) [0|655.35] "s"  IMM
 SG_ Reserved_27 : 56|8@1+ (1,0) [0|255] ""  IMM

BO_ 2332109228 M2I_Byrack_SUMDATA9__28: 8 MBMU
 SG_ CRC_M2I_Byrack_IMM9_28 : 0|8@1+ (1,0) [0|255] ""  IMM
 SG_ M2I_Byrack_HVS_IMM9_28 : 8|16@1+ (0.1,0) [0|6553.5] "v"  IMM
 SG_ M2I_Byrack_Enable_IMM9_28 : 24|2@1+ (1,0) [0|3] ""  IMM
 SG_ M2I_Byrack_ReVeEnable_IMM9_28 : 26|2@1+ (1,0) [0|3] ""  IMM
 SG_ Reserved_28 : 28|4@1+ (1,0) [0|15] ""  IMM
 SG_ M2I_Byrack_IsPostTm_IMM9_28 : 32|8@1+ (0.01,0) [0|2.55] "s"  IMM
 SG_ M2I_Byrack_SysABStTm_IMM9_28 : 40|16@1+ (0.01,0) [0|655.35] "s"  IMM
 SG_ Reserved_28 : 56|8@1+ (1,0) [0|255] ""  IMM

BO_ 2332109229 M2I_Byrack_SUMDATA9__29: 8 MBMU
 SG_ CRC_M2I_Byrack_IMM9_29 : 0|8@1+ (1,0) [0|255] ""  IMM
 SG_ M2I_Byrack_HVS_IMM9_29 : 8|16@1+ (0.1,0) [0|6553.5] "v"  IMM
 SG_ M2I_Byrack_Enable_IMM9_29 : 24|2@1+ (1,0) [0|3] ""  IMM
 SG_ M2I_Byrack_ReVeEnable_IMM9_29 : 26|2@1+ (1,0) [0|3] ""  IMM
 SG_ Reserved_29 : 28|4@1+ (1,0) [0|15] ""  IMM
 SG_ M2I_Byrack_IsPostTm_IMM9_29 : 32|8@1+ (0.01,0) [0|2.55] "s"  IMM
 SG_ M2I_Byrack_SysABStTm_IMM9_29 : 40|16@1+ (0.01,0) [0|655.35] "s"  IMM
 SG_ Reserved_29 : 56|8@1+ (1,0) [0|255] ""  IMM

BO_ 2332109230 M2I_Byrack_SUMDATA9__30: 8 MBMU
 SG_ CRC_M2I_Byrack_IMM9_30 : 0|8@1+ (1,0) [0|255] ""  IMM
 SG_ M2I_Byrack_HVS_IMM9_30 : 8|16@1+ (0.1,0) [0|6553.5] "v"  IMM
 SG_ M2I_Byrack_Enable_IMM9_30 : 24|2@1+ (1,0) [0|3] ""  IMM
 SG_ M2I_Byrack_ReVeEnable_IMM9_30 : 26|2@1+ (1,0) [0|3] ""  IMM
 SG_ Reserved_30 : 28|4@1+ (1,0) [0|15] ""  IMM
 SG_ M2I_Byrack_IsPostTm_IMM9_30 : 32|8@1+ (0.01,0) [0|2.55] "s"  IMM
 SG_ M2I_Byrack_SysABStTm_IMM9_30 : 40|16@1+ (0.01,0) [0|655.35] "s"  IMM
 SG_ Reserved_30 : 56|8@1+ (1,0) [0|255] ""  IMM

BO_ 2332109231 M2I_Byrack_SUMDATA9__31: 8 MBMU
 SG_ CRC_M2I_Byrack_IMM9_31 : 0|8@1+ (1,0) [0|255] ""  IMM
 SG_ M2I_Byrack_HVS_IMM9_31 : 8|16@1+ (0.1,0) [0|6553.5] "v"  IMM
 SG_ M2I_Byrack_Enable_IMM9_31 : 24|2@1+ (1,0) [0|3] ""  IMM
 SG_ M2I_Byrack_ReVeEnable_IMM9_31 : 26|2@1+ (1,0) [0|3] ""  IMM
 SG_ Reserved_31 : 28|4@1+ (1,0) [0|15] ""  IMM
 SG_ M2I_Byrack_IsPostTm_IMM9_31 : 32|8@1+ (0.01,0) [0|2.55] "s"  IMM
 SG_ M2I_Byrack_SysABStTm_IMM9_31 : 40|16@1+ (0.01,0) [0|655.35] "s"  IMM
 SG_ Reserved_31 : 56|8@1+ (1,0) [0|255] ""  IMM

BO_ 2332109457 M2I_Byrack_SUMDATA10__01: 8 MBMU
 SG_ CRC_M2I_Byrack_IMM10_01 : 0|8@1+ (1,0) [0|255] ""  IMM
 SG_ M2I_Byrack_HVS_IMM10_01 : 8|16@1+ (0.1,0) [0|6553.5] "v"  IMM
 SG_ M2I_Byrack_Enable_IMM10_01 : 24|2@1+ (1,0) [0|3] ""  IMM
 SG_ M2I_Byrack_ReVeEnable_IMM10_01 : 26|2@1+ (1,0) [0|3] ""  IMM
 SG_ Reserved_01 : 28|4@1+ (1,0) [0|15] ""  IMM
 SG_ M2I_Byrack_IsPostTm_IMM10_01 : 32|8@1+ (0.01,0) [0|2.55] "s"  IMM
 SG_ M2I_Byrack_SysABStTm_IMM10_01 : 40|16@1+ (0.01,0) [0|655.35] "s"  IMM
 SG_ Reserved_01 : 56|8@1+ (1,0) [0|255] ""  IMM

BO_ 2332109458 M2I_Byrack_SUMDATA10__02: 8 MBMU
 SG_ CRC_M2I_Byrack_IMM10_02 : 0|8@1+ (1,0) [0|255] ""  IMM
 SG_ M2I_Byrack_HVS_IMM10_02 : 8|16@1+ (0.1,0) [0|6553.5] "v"  IMM
 SG_ M2I_Byrack_Enable_IMM10_02 : 24|2@1+ (1,0) [0|3] ""  IMM
 SG_ M2I_Byrack_ReVeEnable_IMM10_02 : 26|2@1+ (1,0) [0|3] ""  IMM
 SG_ Reserved_02 : 28|4@1+ (1,0) [0|15] ""  IMM
 SG_ M2I_Byrack_IsPostTm_IMM10_02 : 32|8@1+ (0.01,0) [0|2.55] "s"  IMM
 SG_ M2I_Byrack_SysABStTm_IMM10_02 : 40|16@1+ (0.01,0) [0|655.35] "s"  IMM
 SG_ Reserved_02 : 56|8@1+ (1,0) [0|255] ""  IMM

BO_ 2332109459 M2I_Byrack_SUMDATA10__03: 8 MBMU
 SG_ CRC_M2I_Byrack_IMM10_03 : 0|8@1+ (1,0) [0|255] ""  IMM
 SG_ M2I_Byrack_HVS_IMM10_03 : 8|16@1+ (0.1,0) [0|6553.5] "v"  IMM
 SG_ M2I_Byrack_Enable_IMM10_03 : 24|2@1+ (1,0) [0|3] ""  IMM
 SG_ M2I_Byrack_ReVeEnable_IMM10_03 : 26|2@1+ (1,0) [0|3] ""  IMM
 SG_ Reserved_03 : 28|4@1+ (1,0) [0|15] ""  IMM
 SG_ M2I_Byrack_IsPostTm_IMM10_03 : 32|8@1+ (0.01,0) [0|2.55] "s"  IMM
 SG_ M2I_Byrack_SysABStTm_IMM10_03 : 40|16@1+ (0.01,0) [0|655.35] "s"  IMM
 SG_ Reserved_03 : 56|8@1+ (1,0) [0|255] ""  IMM

BO_ 2332109460 M2I_Byrack_SUMDATA10__04: 8 MBMU
 SG_ CRC_M2I_Byrack_IMM10_04 : 0|8@1+ (1,0) [0|255] ""  IMM
 SG_ M2I_Byrack_HVS_IMM10_04 : 8|16@1+ (0.1,0) [0|6553.5] "v"  IMM
 SG_ M2I_Byrack_Enable_IMM10_04 : 24|2@1+ (1,0) [0|3] ""  IMM
 SG_ M2I_Byrack_ReVeEnable_IMM10_04 : 26|2@1+ (1,0) [0|3] ""  IMM
 SG_ Reserved_04 : 28|4@1+ (1,0) [0|15] ""  IMM
 SG_ M2I_Byrack_IsPostTm_IMM10_04 : 32|8@1+ (0.01,0) [0|2.55] "s"  IMM
 SG_ M2I_Byrack_SysABStTm_IMM10_04 : 40|16@1+ (0.01,0) [0|655.35] "s"  IMM
 SG_ Reserved_04 : 56|8@1+ (1,0) [0|255] ""  IMM

BO_ 2332109461 M2I_Byrack_SUMDATA10__05: 8 MBMU
 SG_ CRC_M2I_Byrack_IMM10_05 : 0|8@1+ (1,0) [0|255] ""  IMM
 SG_ M2I_Byrack_HVS_IMM10_05 : 8|16@1+ (0.1,0) [0|6553.5] "v"  IMM
 SG_ M2I_Byrack_Enable_IMM10_05 : 24|2@1+ (1,0) [0|3] ""  IMM
 SG_ M2I_Byrack_ReVeEnable_IMM10_05 : 26|2@1+ (1,0) [0|3] ""  IMM
 SG_ Reserved_05 : 28|4@1+ (1,0) [0|15] ""  IMM
 SG_ M2I_Byrack_IsPostTm_IMM10_05 : 32|8@1+ (0.01,0) [0|2.55] "s"  IMM
 SG_ M2I_Byrack_SysABStTm_IMM10_05 : 40|16@1+ (0.01,0) [0|655.35] "s"  IMM
 SG_ Reserved_05 : 56|8@1+ (1,0) [0|255] ""  IMM

BO_ 2332109462 M2I_Byrack_SUMDATA10__06: 8 MBMU
 SG_ CRC_M2I_Byrack_IMM10_06 : 0|8@1+ (1,0) [0|255] ""  IMM
 SG_ M2I_Byrack_HVS_IMM10_06 : 8|16@1+ (0.1,0) [0|6553.5] "v"  IMM
 SG_ M2I_Byrack_Enable_IMM10_06 : 24|2@1+ (1,0) [0|3] ""  IMM
 SG_ M2I_Byrack_ReVeEnable_IMM10_06 : 26|2@1+ (1,0) [0|3] ""  IMM
 SG_ Reserved_06 : 28|4@1+ (1,0) [0|15] ""  IMM
 SG_ M2I_Byrack_IsPostTm_IMM10_06 : 32|8@1+ (0.01,0) [0|2.55] "s"  IMM
 SG_ M2I_Byrack_SysABStTm_IMM10_06 : 40|16@1+ (0.01,0) [0|655.35] "s"  IMM
 SG_ Reserved_06 : 56|8@1+ (1,0) [0|255] ""  IMM

BO_ 2332109463 M2I_Byrack_SUMDATA10__07: 8 MBMU
 SG_ CRC_M2I_Byrack_IMM10_07 : 0|8@1+ (1,0) [0|255] ""  IMM
 SG_ M2I_Byrack_HVS_IMM10_07 : 8|16@1+ (0.1,0) [0|6553.5] "v"  IMM
 SG_ M2I_Byrack_Enable_IMM10_07 : 24|2@1+ (1,0) [0|3] ""  IMM
 SG_ M2I_Byrack_ReVeEnable_IMM10_07 : 26|2@1+ (1,0) [0|3] ""  IMM
 SG_ Reserved_07 : 28|4@1+ (1,0) [0|15] ""  IMM
 SG_ M2I_Byrack_IsPostTm_IMM10_07 : 32|8@1+ (0.01,0) [0|2.55] "s"  IMM
 SG_ M2I_Byrack_SysABStTm_IMM10_07 : 40|16@1+ (0.01,0) [0|655.35] "s"  IMM
 SG_ Reserved_07 : 56|8@1+ (1,0) [0|255] ""  IMM

BO_ 2332109464 M2I_Byrack_SUMDATA10__08: 8 MBMU
 SG_ CRC_M2I_Byrack_IMM10_08 : 0|8@1+ (1,0) [0|255] ""  IMM
 SG_ M2I_Byrack_HVS_IMM10_08 : 8|16@1+ (0.1,0) [0|6553.5] "v"  IMM
 SG_ M2I_Byrack_Enable_IMM10_08 : 24|2@1+ (1,0) [0|3] ""  IMM
 SG_ M2I_Byrack_ReVeEnable_IMM10_08 : 26|2@1+ (1,0) [0|3] ""  IMM
 SG_ Reserved_08 : 28|4@1+ (1,0) [0|15] ""  IMM
 SG_ M2I_Byrack_IsPostTm_IMM10_08 : 32|8@1+ (0.01,0) [0|2.55] "s"  IMM
 SG_ M2I_Byrack_SysABStTm_IMM10_08 : 40|16@1+ (0.01,0) [0|655.35] "s"  IMM
 SG_ Reserved_08 : 56|8@1+ (1,0) [0|255] ""  IMM

BO_ 2332109465 M2I_Byrack_SUMDATA10__09: 8 MBMU
 SG_ CRC_M2I_Byrack_IMM10_09 : 0|8@1+ (1,0) [0|255] ""  IMM
 SG_ M2I_Byrack_HVS_IMM10_09 : 8|16@1+ (0.1,0) [0|6553.5] "v"  IMM
 SG_ M2I_Byrack_Enable_IMM10_09 : 24|2@1+ (1,0) [0|3] ""  IMM
 SG_ M2I_Byrack_ReVeEnable_IMM10_09 : 26|2@1+ (1,0) [0|3] ""  IMM
 SG_ Reserved_09 : 28|4@1+ (1,0) [0|15] ""  IMM
 SG_ M2I_Byrack_IsPostTm_IMM10_09 : 32|8@1+ (0.01,0) [0|2.55] "s"  IMM
 SG_ M2I_Byrack_SysABStTm_IMM10_09 : 40|16@1+ (0.01,0) [0|655.35] "s"  IMM
 SG_ Reserved_09 : 56|8@1+ (1,0) [0|255] ""  IMM

BO_ 2332109466 M2I_Byrack_SUMDATA10__10: 8 MBMU
 SG_ CRC_M2I_Byrack_IMM10_10 : 0|8@1+ (1,0) [0|255] ""  IMM
 SG_ M2I_Byrack_HVS_IMM10_10 : 8|16@1+ (0.1,0) [0|6553.5] "v"  IMM
 SG_ M2I_Byrack_Enable_IMM10_10 : 24|2@1+ (1,0) [0|3] ""  IMM
 SG_ M2I_Byrack_ReVeEnable_IMM10_10 : 26|2@1+ (1,0) [0|3] ""  IMM
 SG_ Reserved_10 : 28|4@1+ (1,0) [0|15] ""  IMM
 SG_ M2I_Byrack_IsPostTm_IMM10_10 : 32|8@1+ (0.01,0) [0|2.55] "s"  IMM
 SG_ M2I_Byrack_SysABStTm_IMM10_10 : 40|16@1+ (0.01,0) [0|655.35] "s"  IMM
 SG_ Reserved_10 : 56|8@1+ (1,0) [0|255] ""  IMM

BO_ 2332109467 M2I_Byrack_SUMDATA10__11: 8 MBMU
 SG_ CRC_M2I_Byrack_IMM10_11 : 0|8@1+ (1,0) [0|255] ""  IMM
 SG_ M2I_Byrack_HVS_IMM10_11 : 8|16@1+ (0.1,0) [0|6553.5] "v"  IMM
 SG_ M2I_Byrack_Enable_IMM10_11 : 24|2@1+ (1,0) [0|3] ""  IMM
 SG_ M2I_Byrack_ReVeEnable_IMM10_11 : 26|2@1+ (1,0) [0|3] ""  IMM
 SG_ Reserved_11 : 28|4@1+ (1,0) [0|15] ""  IMM
 SG_ M2I_Byrack_IsPostTm_IMM10_11 : 32|8@1+ (0.01,0) [0|2.55] "s"  IMM
 SG_ M2I_Byrack_SysABStTm_IMM10_11 : 40|16@1+ (0.01,0) [0|655.35] "s"  IMM
 SG_ Reserved_11 : 56|8@1+ (1,0) [0|255] ""  IMM

BO_ 2332109468 M2I_Byrack_SUMDATA10__12: 8 MBMU
 SG_ CRC_M2I_Byrack_IMM10_12 : 0|8@1+ (1,0) [0|255] ""  IMM
 SG_ M2I_Byrack_HVS_IMM10_12 : 8|16@1+ (0.1,0) [0|6553.5] "v"  IMM
 SG_ M2I_Byrack_Enable_IMM10_12 : 24|2@1+ (1,0) [0|3] ""  IMM
 SG_ M2I_Byrack_ReVeEnable_IMM10_12 : 26|2@1+ (1,0) [0|3] ""  IMM
 SG_ Reserved_12 : 28|4@1+ (1,0) [0|15] ""  IMM
 SG_ M2I_Byrack_IsPostTm_IMM10_12 : 32|8@1+ (0.01,0) [0|2.55] "s"  IMM
 SG_ M2I_Byrack_SysABStTm_IMM10_12 : 40|16@1+ (0.01,0) [0|655.35] "s"  IMM
 SG_ Reserved_12 : 56|8@1+ (1,0) [0|255] ""  IMM

BO_ 2332109469 M2I_Byrack_SUMDATA10__13: 8 MBMU
 SG_ CRC_M2I_Byrack_IMM10_13 : 0|8@1+ (1,0) [0|255] ""  IMM
 SG_ M2I_Byrack_HVS_IMM10_13 : 8|16@1+ (0.1,0) [0|6553.5] "v"  IMM
 SG_ M2I_Byrack_Enable_IMM10_13 : 24|2@1+ (1,0) [0|3] ""  IMM
 SG_ M2I_Byrack_ReVeEnable_IMM10_13 : 26|2@1+ (1,0) [0|3] ""  IMM
 SG_ Reserved_13 : 28|4@1+ (1,0) [0|15] ""  IMM
 SG_ M2I_Byrack_IsPostTm_IMM10_13 : 32|8@1+ (0.01,0) [0|2.55] "s"  IMM
 SG_ M2I_Byrack_SysABStTm_IMM10_13 : 40|16@1+ (0.01,0) [0|655.35] "s"  IMM
 SG_ Reserved_13 : 56|8@1+ (1,0) [0|255] ""  IMM

BO_ 2332109470 M2I_Byrack_SUMDATA10__14: 8 MBMU
 SG_ CRC_M2I_Byrack_IMM10_14 : 0|8@1+ (1,0) [0|255] ""  IMM
 SG_ M2I_Byrack_HVS_IMM10_14 : 8|16@1+ (0.1,0) [0|6553.5] "v"  IMM
 SG_ M2I_Byrack_Enable_IMM10_14 : 24|2@1+ (1,0) [0|3] ""  IMM
 SG_ M2I_Byrack_ReVeEnable_IMM10_14 : 26|2@1+ (1,0) [0|3] ""  IMM
 SG_ Reserved_14 : 28|4@1+ (1,0) [0|15] ""  IMM
 SG_ M2I_Byrack_IsPostTm_IMM10_14 : 32|8@1+ (0.01,0) [0|2.55] "s"  IMM
 SG_ M2I_Byrack_SysABStTm_IMM10_14 : 40|16@1+ (0.01,0) [0|655.35] "s"  IMM
 SG_ Reserved_14 : 56|8@1+ (1,0) [0|255] ""  IMM

BO_ 2332109471 M2I_Byrack_SUMDATA10__15: 8 MBMU
 SG_ CRC_M2I_Byrack_IMM10_15 : 0|8@1+ (1,0) [0|255] ""  IMM
 SG_ M2I_Byrack_HVS_IMM10_15 : 8|16@1+ (0.1,0) [0|6553.5] "v"  IMM
 SG_ M2I_Byrack_Enable_IMM10_15 : 24|2@1+ (1,0) [0|3] ""  IMM
 SG_ M2I_Byrack_ReVeEnable_IMM10_15 : 26|2@1+ (1,0) [0|3] ""  IMM
 SG_ Reserved_15 : 28|4@1+ (1,0) [0|15] ""  IMM
 SG_ M2I_Byrack_IsPostTm_IMM10_15 : 32|8@1+ (0.01,0) [0|2.55] "s"  IMM
 SG_ M2I_Byrack_SysABStTm_IMM10_15 : 40|16@1+ (0.01,0) [0|655.35] "s"  IMM
 SG_ Reserved_15 : 56|8@1+ (1,0) [0|255] ""  IMM

BO_ 2332109472 M2I_Byrack_SUMDATA10__16: 8 MBMU
 SG_ CRC_M2I_Byrack_IMM10_16 : 0|8@1+ (1,0) [0|255] ""  IMM
 SG_ M2I_Byrack_HVS_IMM10_16 : 8|16@1+ (0.1,0) [0|6553.5] "v"  IMM
 SG_ M2I_Byrack_Enable_IMM10_16 : 24|2@1+ (1,0) [0|3] ""  IMM
 SG_ M2I_Byrack_ReVeEnable_IMM10_16 : 26|2@1+ (1,0) [0|3] ""  IMM
 SG_ Reserved_16 : 28|4@1+ (1,0) [0|15] ""  IMM
 SG_ M2I_Byrack_IsPostTm_IMM10_16 : 32|8@1+ (0.01,0) [0|2.55] "s"  IMM
 SG_ M2I_Byrack_SysABStTm_IMM10_16 : 40|16@1+ (0.01,0) [0|655.35] "s"  IMM
 SG_ Reserved_16 : 56|8@1+ (1,0) [0|255] ""  IMM

BO_ 2332109473 M2I_Byrack_SUMDATA10__17: 8 MBMU
 SG_ CRC_M2I_Byrack_IMM10_17 : 0|8@1+ (1,0) [0|255] ""  IMM
 SG_ M2I_Byrack_HVS_IMM10_17 : 8|16@1+ (0.1,0) [0|6553.5] "v"  IMM
 SG_ M2I_Byrack_Enable_IMM10_17 : 24|2@1+ (1,0) [0|3] ""  IMM
 SG_ M2I_Byrack_ReVeEnable_IMM10_17 : 26|2@1+ (1,0) [0|3] ""  IMM
 SG_ Reserved_17 : 28|4@1+ (1,0) [0|15] ""  IMM
 SG_ M2I_Byrack_IsPostTm_IMM10_17 : 32|8@1+ (0.01,0) [0|2.55] "s"  IMM
 SG_ M2I_Byrack_SysABStTm_IMM10_17 : 40|16@1+ (0.01,0) [0|655.35] "s"  IMM
 SG_ Reserved_17 : 56|8@1+ (1,0) [0|255] ""  IMM

BO_ 2332109474 M2I_Byrack_SUMDATA10__18: 8 MBMU
 SG_ CRC_M2I_Byrack_IMM10_18 : 0|8@1+ (1,0) [0|255] ""  IMM
 SG_ M2I_Byrack_HVS_IMM10_18 : 8|16@1+ (0.1,0) [0|6553.5] "v"  IMM
 SG_ M2I_Byrack_Enable_IMM10_18 : 24|2@1+ (1,0) [0|3] ""  IMM
 SG_ M2I_Byrack_ReVeEnable_IMM10_18 : 26|2@1+ (1,0) [0|3] ""  IMM
 SG_ Reserved_18 : 28|4@1+ (1,0) [0|15] ""  IMM
 SG_ M2I_Byrack_IsPostTm_IMM10_18 : 32|8@1+ (0.01,0) [0|2.55] "s"  IMM
 SG_ M2I_Byrack_SysABStTm_IMM10_18 : 40|16@1+ (0.01,0) [0|655.35] "s"  IMM
 SG_ Reserved_18 : 56|8@1+ (1,0) [0|255] ""  IMM

BO_ 2332109475 M2I_Byrack_SUMDATA10__19: 8 MBMU
 SG_ CRC_M2I_Byrack_IMM10_19 : 0|8@1+ (1,0) [0|255] ""  IMM
 SG_ M2I_Byrack_HVS_IMM10_19 : 8|16@1+ (0.1,0) [0|6553.5] "v"  IMM
 SG_ M2I_Byrack_Enable_IMM10_19 : 24|2@1+ (1,0) [0|3] ""  IMM
 SG_ M2I_Byrack_ReVeEnable_IMM10_19 : 26|2@1+ (1,0) [0|3] ""  IMM
 SG_ Reserved_19 : 28|4@1+ (1,0) [0|15] ""  IMM
 SG_ M2I_Byrack_IsPostTm_IMM10_19 : 32|8@1+ (0.01,0) [0|2.55] "s"  IMM
 SG_ M2I_Byrack_SysABStTm_IMM10_19 : 40|16@1+ (0.01,0) [0|655.35] "s"  IMM
 SG_ Reserved_19 : 56|8@1+ (1,0) [0|255] ""  IMM

BO_ 2332109476 M2I_Byrack_SUMDATA10__20: 8 MBMU
 SG_ CRC_M2I_Byrack_IMM10_20 : 0|8@1+ (1,0) [0|255] ""  IMM
 SG_ M2I_Byrack_HVS_IMM10_20 : 8|16@1+ (0.1,0) [0|6553.5] "v"  IMM
 SG_ M2I_Byrack_Enable_IMM10_20 : 24|2@1+ (1,0) [0|3] ""  IMM
 SG_ M2I_Byrack_ReVeEnable_IMM10_20 : 26|2@1+ (1,0) [0|3] ""  IMM
 SG_ Reserved_20 : 28|4@1+ (1,0) [0|15] ""  IMM
 SG_ M2I_Byrack_IsPostTm_IMM10_20 : 32|8@1+ (0.01,0) [0|2.55] "s"  IMM
 SG_ M2I_Byrack_SysABStTm_IMM10_20 : 40|16@1+ (0.01,0) [0|655.35] "s"  IMM
 SG_ Reserved_20 : 56|8@1+ (1,0) [0|255] ""  IMM

BO_ 2332109477 M2I_Byrack_SUMDATA10__21: 8 MBMU
 SG_ CRC_M2I_Byrack_IMM10_21 : 0|8@1+ (1,0) [0|255] ""  IMM
 SG_ M2I_Byrack_HVS_IMM10_21 : 8|16@1+ (0.1,0) [0|6553.5] "v"  IMM
 SG_ M2I_Byrack_Enable_IMM10_21 : 24|2@1+ (1,0) [0|3] ""  IMM
 SG_ M2I_Byrack_ReVeEnable_IMM10_21 : 26|2@1+ (1,0) [0|3] ""  IMM
 SG_ Reserved_21 : 28|4@1+ (1,0) [0|15] ""  IMM
 SG_ M2I_Byrack_IsPostTm_IMM10_21 : 32|8@1+ (0.01,0) [0|2.55] "s"  IMM
 SG_ M2I_Byrack_SysABStTm_IMM10_21 : 40|16@1+ (0.01,0) [0|655.35] "s"  IMM
 SG_ Reserved_21 : 56|8@1+ (1,0) [0|255] ""  IMM

BO_ 2332109478 M2I_Byrack_SUMDATA10__22: 8 MBMU
 SG_ CRC_M2I_Byrack_IMM10_22 : 0|8@1+ (1,0) [0|255] ""  IMM
 SG_ M2I_Byrack_HVS_IMM10_22 : 8|16@1+ (0.1,0) [0|6553.5] "v"  IMM
 SG_ M2I_Byrack_Enable_IMM10_22 : 24|2@1+ (1,0) [0|3] ""  IMM
 SG_ M2I_Byrack_ReVeEnable_IMM10_22 : 26|2@1+ (1,0) [0|3] ""  IMM
 SG_ Reserved_22 : 28|4@1+ (1,0) [0|15] ""  IMM
 SG_ M2I_Byrack_IsPostTm_IMM10_22 : 32|8@1+ (0.01,0) [0|2.55] "s"  IMM
 SG_ M2I_Byrack_SysABStTm_IMM10_22 : 40|16@1+ (0.01,0) [0|655.35] "s"  IMM
 SG_ Reserved_22 : 56|8@1+ (1,0) [0|255] ""  IMM

BO_ 2332109479 M2I_Byrack_SUMDATA10__23: 8 MBMU
 SG_ CRC_M2I_Byrack_IMM10_23 : 0|8@1+ (1,0) [0|255] ""  IMM
 SG_ M2I_Byrack_HVS_IMM10_23 : 8|16@1+ (0.1,0) [0|6553.5] "v"  IMM
 SG_ M2I_Byrack_Enable_IMM10_23 : 24|2@1+ (1,0) [0|3] ""  IMM
 SG_ M2I_Byrack_ReVeEnable_IMM10_23 : 26|2@1+ (1,0) [0|3] ""  IMM
 SG_ Reserved_23 : 28|4@1+ (1,0) [0|15] ""  IMM
 SG_ M2I_Byrack_IsPostTm_IMM10_23 : 32|8@1+ (0.01,0) [0|2.55] "s"  IMM
 SG_ M2I_Byrack_SysABStTm_IMM10_23 : 40|16@1+ (0.01,0) [0|655.35] "s"  IMM
 SG_ Reserved_23 : 56|8@1+ (1,0) [0|255] ""  IMM

BO_ 2332109480 M2I_Byrack_SUMDATA10__24: 8 MBMU
 SG_ CRC_M2I_Byrack_IMM10_24 : 0|8@1+ (1,0) [0|255] ""  IMM
 SG_ M2I_Byrack_HVS_IMM10_24 : 8|16@1+ (0.1,0) [0|6553.5] "v"  IMM
 SG_ M2I_Byrack_Enable_IMM10_24 : 24|2@1+ (1,0) [0|3] ""  IMM
 SG_ M2I_Byrack_ReVeEnable_IMM10_24 : 26|2@1+ (1,0) [0|3] ""  IMM
 SG_ Reserved_24 : 28|4@1+ (1,0) [0|15] ""  IMM
 SG_ M2I_Byrack_IsPostTm_IMM10_24 : 32|8@1+ (0.01,0) [0|2.55] "s"  IMM
 SG_ M2I_Byrack_SysABStTm_IMM10_24 : 40|16@1+ (0.01,0) [0|655.35] "s"  IMM
 SG_ Reserved_24 : 56|8@1+ (1,0) [0|255] ""  IMM

BO_ 2332109481 M2I_Byrack_SUMDATA10__25: 8 MBMU
 SG_ CRC_M2I_Byrack_IMM10_25 : 0|8@1+ (1,0) [0|255] ""  IMM
 SG_ M2I_Byrack_HVS_IMM10_25 : 8|16@1+ (0.1,0) [0|6553.5] "v"  IMM
 SG_ M2I_Byrack_Enable_IMM10_25 : 24|2@1+ (1,0) [0|3] ""  IMM
 SG_ M2I_Byrack_ReVeEnable_IMM10_25 : 26|2@1+ (1,0) [0|3] ""  IMM
 SG_ Reserved_25 : 28|4@1+ (1,0) [0|15] ""  IMM
 SG_ M2I_Byrack_IsPostTm_IMM10_25 : 32|8@1+ (0.01,0) [0|2.55] "s"  IMM
 SG_ M2I_Byrack_SysABStTm_IMM10_25 : 40|16@1+ (0.01,0) [0|655.35] "s"  IMM
 SG_ Reserved_25 : 56|8@1+ (1,0) [0|255] ""  IMM

BO_ 2332109482 M2I_Byrack_SUMDATA10__26: 8 MBMU
 SG_ CRC_M2I_Byrack_IMM10_26 : 0|8@1+ (1,0) [0|255] ""  IMM
 SG_ M2I_Byrack_HVS_IMM10_26 : 8|16@1+ (0.1,0) [0|6553.5] "v"  IMM
 SG_ M2I_Byrack_Enable_IMM10_26 : 24|2@1+ (1,0) [0|3] ""  IMM
 SG_ M2I_Byrack_ReVeEnable_IMM10_26 : 26|2@1+ (1,0) [0|3] ""  IMM
 SG_ Reserved_26 : 28|4@1+ (1,0) [0|15] ""  IMM
 SG_ M2I_Byrack_IsPostTm_IMM10_26 : 32|8@1+ (0.01,0) [0|2.55] "s"  IMM
 SG_ M2I_Byrack_SysABStTm_IMM10_26 : 40|16@1+ (0.01,0) [0|655.35] "s"  IMM
 SG_ Reserved_26 : 56|8@1+ (1,0) [0|255] ""  IMM

BO_ 2332109483 M2I_Byrack_SUMDATA10__27: 8 MBMU
 SG_ CRC_M2I_Byrack_IMM10_27 : 0|8@1+ (1,0) [0|255] ""  IMM
 SG_ M2I_Byrack_HVS_IMM10_27 : 8|16@1+ (0.1,0) [0|6553.5] "v"  IMM
 SG_ M2I_Byrack_Enable_IMM10_27 : 24|2@1+ (1,0) [0|3] ""  IMM
 SG_ M2I_Byrack_ReVeEnable_IMM10_27 : 26|2@1+ (1,0) [0|3] ""  IMM
 SG_ Reserved_27 : 28|4@1+ (1,0) [0|15] ""  IMM
 SG_ M2I_Byrack_IsPostTm_IMM10_27 : 32|8@1+ (0.01,0) [0|2.55] "s"  IMM
 SG_ M2I_Byrack_SysABStTm_IMM10_27 : 40|16@1+ (0.01,0) [0|655.35] "s"  IMM
 SG_ Reserved_27 : 56|8@1+ (1,0) [0|255] ""  IMM

CM_ SG_ 2332108191 CRC_M2I_Byrack_IMM5_15 "CRC校验_IMM5";
CM_ SG_ 2332108191 M2I_Byrack_HVS_IMM5_15 "绝缘测量电压_IMM5";
CM_ SG_ 2332108191 M2I_Byrack_Enable_IMM5_15 "绝缘采样使能位_IMM5";
CM_ SG_ 2332108191 M2I_Byrack_ReVeEnable_IMM5_15 "读取软件版本使能位_IMM5";
CM_ SG_ 2332108191 Reserved_15 "预留预留";
CM_ SG_ 2332108191 M2I_Byrack_IsPostTm_IMM5_15 "绝缘采样时间_IMM5";
CM_ SG_ 2332108191 M2I_Byrack_SysABStTm_IMM5_15 "电压稳定时间_IMM5";
CM_ SG_ 2332108192 CRC_M2I_Byrack_IMM5_16 "CRC校验_IMM5";
CM_ SG_ 2332108192 M2I_Byrack_HVS_IMM5_16 "绝缘测量电压_IMM5";
CM_ SG_ 2332108192 M2I_Byrack_Enable_IMM5_16 "绝缘采样使能位_IMM5";
CM_ SG_ 2332108192 M2I_Byrack_ReVeEnable_IMM5_16 "读取软件版本使能位_IMM5";
CM_ SG_ 2332108192 Reserved_16 "预留预留";
CM_ SG_ 2332108192 M2I_Byrack_IsPostTm_IMM5_16 "绝缘采样时间_IMM5";
CM_ SG_ 2332108192 M2I_Byrack_SysABStTm_IMM5_16 "电压稳定时间_IMM5";
CM_ SG_ 2332108193 CRC_M2I_Byrack_IMM5_17 "CRC校验_IMM5";
CM_ SG_ 2332108193 M2I_Byrack_HVS_IMM5_17 "绝缘测量电压_IMM5";
CM_ SG_ 2332108193 M2I_Byrack_Enable_IMM5_17 "绝缘采样使能位_IMM5";
CM_ SG_ 2332108193 M2I_Byrack_ReVeEnable_IMM5_17 "读取软件版本使能位_IMM5";
CM_ SG_ 2332108193 Reserved_17 "预留预留";
CM_ SG_ 2332108193 M2I_Byrack_IsPostTm_IMM5_17 "绝缘采样时间_IMM5";
CM_ SG_ 2332108193 M2I_Byrack_SysABStTm_IMM5_17 "电压稳定时间_IMM5";
CM_ SG_ 2332108194 CRC_M2I_Byrack_IMM5_18 "CRC校验_IMM5";
CM_ SG_ 2332108194 M2I_Byrack_HVS_IMM5_18 "绝缘测量电压_IMM5";
CM_ SG_ 2332108194 M2I_Byrack_Enable_IMM5_18 "绝缘采样使能位_IMM5";
CM_ SG_ 2332108194 M2I_Byrack_ReVeEnable_IMM5_18 "读取软件版本使能位_IMM5";
CM_ SG_ 2332108194 Reserved_18 "预留预留";
CM_ SG_ 2332108194 M2I_Byrack_IsPostTm_IMM5_18 "绝缘采样时间_IMM5";
CM_ SG_ 2332108194 M2I_Byrack_SysABStTm_IMM5_18 "电压稳定时间_IMM5";
CM_ SG_ 2332108195 CRC_M2I_Byrack_IMM5_19 "CRC校验_IMM5";
CM_ SG_ 2332108195 M2I_Byrack_HVS_IMM5_19 "绝缘测量电压_IMM5";
CM_ SG_ 2332108195 M2I_Byrack_Enable_IMM5_19 "绝缘采样使能位_IMM5";
CM_ SG_ 2332108195 M2I_Byrack_ReVeEnable_IMM5_19 "读取软件版本使能位_IMM5";
CM_ SG_ 2332108195 Reserved_19 "预留预留";
CM_ SG_ 2332108195 M2I_Byrack_IsPostTm_IMM5_19 "绝缘采样时间_IMM5";
CM_ SG_ 2332108195 M2I_Byrack_SysABStTm_IMM5_19 "电压稳定时间_IMM5";
CM_ SG_ 2332108196 CRC_M2I_Byrack_IMM5_20 "CRC校验_IMM5";
CM_ SG_ 2332108196 M2I_Byrack_HVS_IMM5_20 "绝缘测量电压_IMM5";
CM_ SG_ 2332108196 M2I_Byrack_Enable_IMM5_20 "绝缘采样使能位_IMM5";
CM_ SG_ 2332108196 M2I_Byrack_ReVeEnable_IMM5_20 "读取软件版本使能位_IMM5";
CM_ SG_ 2332108196 Reserved_20 "预留预留";
CM_ SG_ 2332108196 M2I_Byrack_IsPostTm_IMM5_20 "绝缘采样时间_IMM5";
CM_ SG_ 2332108196 M2I_Byrack_SysABStTm_IMM5_20 "电压稳定时间_IMM5";
CM_ SG_ 2332108197 CRC_M2I_Byrack_IMM5_21 "CRC校验_IMM5";
CM_ SG_ 2332108197 M2I_Byrack_HVS_IMM5_21 "绝缘测量电压_IMM5";
CM_ SG_ 2332108197 M2I_Byrack_Enable_IMM5_21 "绝缘采样使能位_IMM5";
CM_ SG_ 2332108197 M2I_Byrack_ReVeEnable_IMM5_21 "读取软件版本使能位_IMM5";
CM_ SG_ 2332108197 Reserved_21 "预留预留";
CM_ SG_ 2332108197 M2I_Byrack_IsPostTm_IMM5_21 "绝缘采样时间_IMM5";
CM_ SG_ 2332108197 M2I_Byrack_SysABStTm_IMM5_21 "电压稳定时间_IMM5";
CM_ SG_ 2332108198 CRC_M2I_Byrack_IMM5_22 "CRC校验_IMM5";
CM_ SG_ 2332108198 M2I_Byrack_HVS_IMM5_22 "绝缘测量电压_IMM5";
CM_ SG_ 2332108198 M2I_Byrack_Enable_IMM5_22 "绝缘采样使能位_IMM5";
CM_ SG_ 2332108198 M2I_Byrack_ReVeEnable_IMM5_22 "读取软件版本使能位_IMM5";
CM_ SG_ 2332108198 Reserved_22 "预留预留";
CM_ SG_ 2332108198 M2I_Byrack_IsPostTm_IMM5_22 "绝缘采样时间_IMM5";
CM_ SG_ 2332108198 M2I_Byrack_SysABStTm_IMM5_22 "电压稳定时间_IMM5";
CM_ SG_ 2332108199 CRC_M2I_Byrack_IMM5_23 "CRC校验_IMM5";
CM_ SG_ 2332108199 M2I_Byrack_HVS_IMM5_23 "绝缘测量电压_IMM5";
CM_ SG_ 2332108199 M2I_Byrack_Enable_IMM5_23 "绝缘采样使能位_IMM5";
CM_ SG_ 2332108199 M2I_Byrack_ReVeEnable_IMM5_23 "读取软件版本使能位_IMM5";
CM_ SG_ 2332108199 Reserved_23 "预留预留";
CM_ SG_ 2332108199 M2I_Byrack_IsPostTm_IMM5_23 "绝缘采样时间_IMM5";
CM_ SG_ 2332108199 M2I_Byrack_SysABStTm_IMM5_23 "电压稳定时间_IMM5";
CM_ SG_ 2332108200 CRC_M2I_Byrack_IMM5_24 "CRC校验_IMM5";
CM_ SG_ 2332108200 M2I_Byrack_HVS_IMM5_24 "绝缘测量电压_IMM5";
CM_ SG_ 2332108200 M2I_Byrack_Enable_IMM5_24 "绝缘采样使能位_IMM5";
CM_ SG_ 2332108200 M2I_Byrack_ReVeEnable_IMM5_24 "读取软件版本使能位_IMM5";
CM_ SG_ 2332108200 Reserved_24 "预留预留";
CM_ SG_ 2332108200 M2I_Byrack_IsPostTm_IMM5_24 "绝缘采样时间_IMM5";
CM_ SG_ 2332108200 M2I_Byrack_SysABStTm_IMM5_24 "电压稳定时间_IMM5";
CM_ SG_ 2332108201 CRC_M2I_Byrack_IMM5_25 "CRC校验_IMM5";
CM_ SG_ 2332108201 M2I_Byrack_HVS_IMM5_25 "绝缘测量电压_IMM5";
CM_ SG_ 2332108201 M2I_Byrack_Enable_IMM5_25 "绝缘采样使能位_IMM5";
CM_ SG_ 2332108201 M2I_Byrack_ReVeEnable_IMM5_25 "读取软件版本使能位_IMM5";
CM_ SG_ 2332108201 Reserved_25 "预留预留";
CM_ SG_ 2332108201 M2I_Byrack_IsPostTm_IMM5_25 "绝缘采样时间_IMM5";
CM_ SG_ 2332108201 M2I_Byrack_SysABStTm_IMM5_25 "电压稳定时间_IMM5";
CM_ SG_ 2332108202 CRC_M2I_Byrack_IMM5_26 "CRC校验_IMM5";
CM_ SG_ 2332108202 M2I_Byrack_HVS_IMM5_26 "绝缘测量电压_IMM5";
CM_ SG_ 2332108202 M2I_Byrack_Enable_IMM5_26 "绝缘采样使能位_IMM5";
CM_ SG_ 2332108202 M2I_Byrack_ReVeEnable_IMM5_26 "读取软件版本使能位_IMM5";
CM_ SG_ 2332108202 Reserved_26 "预留预留";
CM_ SG_ 2332108202 M2I_Byrack_IsPostTm_IMM5_26 "绝缘采样时间_IMM5";
CM_ SG_ 2332108202 M2I_Byrack_SysABStTm_IMM5_26 "电压稳定时间_IMM5";
CM_ SG_ 2332108203 CRC_M2I_Byrack_IMM5_27 "CRC校验_IMM5";
CM_ SG_ 2332108203 M2I_Byrack_HVS_IMM5_27 "绝缘测量电压_IMM5";
CM_ SG_ 2332108203 M2I_Byrack_Enable_IMM5_27 "绝缘采样使能位_IMM5";
CM_ SG_ 2332108203 M2I_Byrack_ReVeEnable_IMM5_27 "读取软件版本使能位_IMM5";
CM_ SG_ 2332108203 Reserved_27 "预留预留";
CM_ SG_ 2332108203 M2I_Byrack_IsPostTm_IMM5_27 "绝缘采样时间_IMM5";
CM_ SG_ 2332108203 M2I_Byrack_SysABStTm_IMM5_27 "电压稳定时间_IMM5";
CM_ SG_ 2332108204 CRC_M2I_Byrack_IMM5_28 "CRC校验_IMM5";
CM_ SG_ 2332108204 M2I_Byrack_HVS_IMM5_28 "绝缘测量电压_IMM5";
CM_ SG_ 2332108204 M2I_Byrack_Enable_IMM5_28 "绝缘采样使能位_IMM5";
CM_ SG_ 2332108204 M2I_Byrack_ReVeEnable_IMM5_28 "读取软件版本使能位_IMM5";
CM_ SG_ 2332108204 Reserved_28 "预留预留";
CM_ SG_ 2332108204 M2I_Byrack_IsPostTm_IMM5_28 "绝缘采样时间_IMM5";
CM_ SG_ 2332108204 M2I_Byrack_SysABStTm_IMM5_28 "电压稳定时间_IMM5";
CM_ SG_ 2332108205 CRC_M2I_Byrack_IMM5_29 "CRC校验_IMM5";
CM_ SG_ 2332108205 M2I_Byrack_HVS_IMM5_29 "绝缘测量电压_IMM5";
CM_ SG_ 2332108205 M2I_Byrack_Enable_IMM5_29 "绝缘采样使能位_IMM5";
CM_ SG_ 2332108205 M2I_Byrack_ReVeEnable_IMM5_29 "读取软件版本使能位_IMM5";
CM_ SG_ 2332108205 Reserved_29 "预留预留";
CM_ SG_ 2332108205 M2I_Byrack_IsPostTm_IMM5_29 "绝缘采样时间_IMM5";
CM_ SG_ 2332108205 M2I_Byrack_SysABStTm_IMM5_29 "电压稳定时间_IMM5";
CM_ SG_ 2332108206 CRC_M2I_Byrack_IMM5_30 "CRC校验_IMM5";
CM_ SG_ 2332108206 M2I_Byrack_HVS_IMM5_30 "绝缘测量电压_IMM5";
CM_ SG_ 2332108206 M2I_Byrack_Enable_IMM5_30 "绝缘采样使能位_IMM5";
CM_ SG_ 2332108206 M2I_Byrack_ReVeEnable_IMM5_30 "读取软件版本使能位_IMM5";
CM_ SG_ 2332108206 Reserved_30 "预留预留";
CM_ SG_ 2332108206 M2I_Byrack_IsPostTm_IMM5_30 "绝缘采样时间_IMM5";
CM_ SG_ 2332108206 M2I_Byrack_SysABStTm_IMM5_30 "电压稳定时间_IMM5";
CM_ SG_ 2332108207 CRC_M2I_Byrack_IMM5_31 "CRC校验_IMM5";
CM_ SG_ 2332108207 M2I_Byrack_HVS_IMM5_31 "绝缘测量电压_IMM5";
CM_ SG_ 2332108207 M2I_Byrack_Enable_IMM5_31 "绝缘采样使能位_IMM5";
CM_ SG_ 2332108207 M2I_Byrack_ReVeEnable_IMM5_31 "读取软件版本使能位_IMM5";
CM_ SG_ 2332108207 Reserved_31 "预留预留";
CM_ SG_ 2332108207 M2I_Byrack_IsPostTm_IMM5_31 "绝缘采样时间_IMM5";
CM_ SG_ 2332108207 M2I_Byrack_SysABStTm_IMM5_31 "电压稳定时间_IMM5";
CM_ SG_ 2332108433 CRC_M2I_Byrack_IMM6_01 "CRC校验_IMM6";
CM_ SG_ 2332108433 M2I_Byrack_HVS_IMM6_01 "绝缘测量电压_IMM6";
CM_ SG_ 2332108433 M2I_Byrack_Enable_IMM6_01 "绝缘采样使能位_IMM6";
CM_ SG_ 2332108433 M2I_Byrack_ReVeEnable_IMM6_01 "读取软件版本使能位_IMM6";
CM_ SG_ 2332108433 Reserved_01 "预留预留";
CM_ SG_ 2332108433 M2I_Byrack_IsPostTm_IMM6_01 "绝缘采样时间_IMM6";
CM_ SG_ 2332108433 M2I_Byrack_SysABStTm_IMM6_01 "电压稳定时间_IMM6";
CM_ SG_ 2332108434 CRC_M2I_Byrack_IMM6_02 "CRC校验_IMM6";
CM_ SG_ 2332108434 M2I_Byrack_HVS_IMM6_02 "绝缘测量电压_IMM6";
CM_ SG_ 2332108434 M2I_Byrack_Enable_IMM6_02 "绝缘采样使能位_IMM6";
CM_ SG_ 2332108434 M2I_Byrack_ReVeEnable_IMM6_02 "读取软件版本使能位_IMM6";
CM_ SG_ 2332108434 Reserved_02 "预留预留";
CM_ SG_ 2332108434 M2I_Byrack_IsPostTm_IMM6_02 "绝缘采样时间_IMM6";
CM_ SG_ 2332108434 M2I_Byrack_SysABStTm_IMM6_02 "电压稳定时间_IMM6";
CM_ SG_ 2332108435 CRC_M2I_Byrack_IMM6_03 "CRC校验_IMM6";
CM_ SG_ 2332108435 M2I_Byrack_HVS_IMM6_03 "绝缘测量电压_IMM6";
CM_ SG_ 2332108435 M2I_Byrack_Enable_IMM6_03 "绝缘采样使能位_IMM6";
CM_ SG_ 2332108435 M2I_Byrack_ReVeEnable_IMM6_03 "读取软件版本使能位_IMM6";
CM_ SG_ 2332108435 Reserved_03 "预留预留";
CM_ SG_ 2332108435 M2I_Byrack_IsPostTm_IMM6_03 "绝缘采样时间_IMM6";
CM_ SG_ 2332108435 M2I_Byrack_SysABStTm_IMM6_03 "电压稳定时间_IMM6";
CM_ SG_ 2332108436 CRC_M2I_Byrack_IMM6_04 "CRC校验_IMM6";
CM_ SG_ 2332108436 M2I_Byrack_HVS_IMM6_04 "绝缘测量电压_IMM6";
CM_ SG_ 2332108436 M2I_Byrack_Enable_IMM6_04 "绝缘采样使能位_IMM6";
CM_ SG_ 2332108436 M2I_Byrack_ReVeEnable_IMM6_04 "读取软件版本使能位_IMM6";
CM_ SG_ 2332108436 Reserved_04 "预留预留";
CM_ SG_ 2332108436 M2I_Byrack_IsPostTm_IMM6_04 "绝缘采样时间_IMM6";
CM_ SG_ 2332108436 M2I_Byrack_SysABStTm_IMM6_04 "电压稳定时间_IMM6";
CM_ SG_ 2332108437 CRC_M2I_Byrack_IMM6_05 "CRC校验_IMM6";
CM_ SG_ 2332108437 M2I_Byrack_HVS_IMM6_05 "绝缘测量电压_IMM6";
CM_ SG_ 2332108437 M2I_Byrack_Enable_IMM6_05 "绝缘采样使能位_IMM6";
CM_ SG_ 2332108437 M2I_Byrack_ReVeEnable_IMM6_05 "读取软件版本使能位_IMM6";
CM_ SG_ 2332108437 Reserved_05 "预留预留";
CM_ SG_ 2332108437 M2I_Byrack_IsPostTm_IMM6_05 "绝缘采样时间_IMM6";
CM_ SG_ 2332108437 M2I_Byrack_SysABStTm_IMM6_05 "电压稳定时间_IMM6";
CM_ SG_ 2332108438 CRC_M2I_Byrack_IMM6_06 "CRC校验_IMM6";
CM_ SG_ 2332108438 M2I_Byrack_HVS_IMM6_06 "绝缘测量电压_IMM6";
CM_ SG_ 2332108438 M2I_Byrack_Enable_IMM6_06 "绝缘采样使能位_IMM6";
CM_ SG_ 2332108438 M2I_Byrack_ReVeEnable_IMM6_06 "读取软件版本使能位_IMM6";
CM_ SG_ 2332108438 Reserved_06 "预留预留";
CM_ SG_ 2332108438 M2I_Byrack_IsPostTm_IMM6_06 "绝缘采样时间_IMM6";
CM_ SG_ 2332108438 M2I_Byrack_SysABStTm_IMM6_06 "电压稳定时间_IMM6";
CM_ SG_ 2332108439 CRC_M2I_Byrack_IMM6_07 "CRC校验_IMM6";
CM_ SG_ 2332108439 M2I_Byrack_HVS_IMM6_07 "绝缘测量电压_IMM6";
CM_ SG_ 2332108439 M2I_Byrack_Enable_IMM6_07 "绝缘采样使能位_IMM6";
CM_ SG_ 2332108439 M2I_Byrack_ReVeEnable_IMM6_07 "读取软件版本使能位_IMM6";
CM_ SG_ 2332108439 Reserved_07 "预留预留";
CM_ SG_ 2332108439 M2I_Byrack_IsPostTm_IMM6_07 "绝缘采样时间_IMM6";
CM_ SG_ 2332108439 M2I_Byrack_SysABStTm_IMM6_07 "电压稳定时间_IMM6";
CM_ SG_ 2332108440 CRC_M2I_Byrack_IMM6_08 "CRC校验_IMM6";
CM_ SG_ 2332108440 M2I_Byrack_HVS_IMM6_08 "绝缘测量电压_IMM6";
CM_ SG_ 2332108440 M2I_Byrack_Enable_IMM6_08 "绝缘采样使能位_IMM6";
CM_ SG_ 2332108440 M2I_Byrack_ReVeEnable_IMM6_08 "读取软件版本使能位_IMM6";
CM_ SG_ 2332108440 Reserved_08 "预留预留";
CM_ SG_ 2332108440 M2I_Byrack_IsPostTm_IMM6_08 "绝缘采样时间_IMM6";
CM_ SG_ 2332108440 M2I_Byrack_SysABStTm_IMM6_08 "电压稳定时间_IMM6";
CM_ SG_ 2332108441 CRC_M2I_Byrack_IMM6_09 "CRC校验_IMM6";
CM_ SG_ 2332108441 M2I_Byrack_HVS_IMM6_09 "绝缘测量电压_IMM6";
CM_ SG_ 2332108441 M2I_Byrack_Enable_IMM6_09 "绝缘采样使能位_IMM6";
CM_ SG_ 2332108441 M2I_Byrack_ReVeEnable_IMM6_09 "读取软件版本使能位_IMM6";
CM_ SG_ 2332108441 Reserved_09 "预留预留";
CM_ SG_ 2332108441 M2I_Byrack_IsPostTm_IMM6_09 "绝缘采样时间_IMM6";
CM_ SG_ 2332108441 M2I_Byrack_SysABStTm_IMM6_09 "电压稳定时间_IMM6";
CM_ SG_ 2332108442 CRC_M2I_Byrack_IMM6_10 "CRC校验_IMM6";
CM_ SG_ 2332108442 M2I_Byrack_HVS_IMM6_10 "绝缘测量电压_IMM6";
CM_ SG_ 2332108442 M2I_Byrack_Enable_IMM6_10 "绝缘采样使能位_IMM6";
CM_ SG_ 2332108442 M2I_Byrack_ReVeEnable_IMM6_10 "读取软件版本使能位_IMM6";
CM_ SG_ 2332108442 Reserved_10 "预留预留";
CM_ SG_ 2332108442 M2I_Byrack_IsPostTm_IMM6_10 "绝缘采样时间_IMM6";
CM_ SG_ 2332108442 M2I_Byrack_SysABStTm_IMM6_10 "电压稳定时间_IMM6";
CM_ SG_ 2332108443 CRC_M2I_Byrack_IMM6_11 "CRC校验_IMM6";
CM_ SG_ 2332108443 M2I_Byrack_HVS_IMM6_11 "绝缘测量电压_IMM6";
CM_ SG_ 2332108443 M2I_Byrack_Enable_IMM6_11 "绝缘采样使能位_IMM6";
CM_ SG_ 2332108443 M2I_Byrack_ReVeEnable_IMM6_11 "读取软件版本使能位_IMM6";
CM_ SG_ 2332108443 Reserved_11 "预留预留";
CM_ SG_ 2332108443 M2I_Byrack_IsPostTm_IMM6_11 "绝缘采样时间_IMM6";
CM_ SG_ 2332108443 M2I_Byrack_SysABStTm_IMM6_11 "电压稳定时间_IMM6";
CM_ SG_ 2332108444 CRC_M2I_Byrack_IMM6_12 "CRC校验_IMM6";
CM_ SG_ 2332108444 M2I_Byrack_HVS_IMM6_12 "绝缘测量电压_IMM6";
CM_ SG_ 2332108444 M2I_Byrack_Enable_IMM6_12 "绝缘采样使能位_IMM6";
CM_ SG_ 2332108444 M2I_Byrack_ReVeEnable_IMM6_12 "读取软件版本使能位_IMM6";
CM_ SG_ 2332108444 Reserved_12 "预留预留";
CM_ SG_ 2332108444 M2I_Byrack_IsPostTm_IMM6_12 "绝缘采样时间_IMM6";
CM_ SG_ 2332108444 M2I_Byrack_SysABStTm_IMM6_12 "电压稳定时间_IMM6";
CM_ SG_ 2332108445 CRC_M2I_Byrack_IMM6_13 "CRC校验_IMM6";
CM_ SG_ 2332108445 M2I_Byrack_HVS_IMM6_13 "绝缘测量电压_IMM6";
CM_ SG_ 2332108445 M2I_Byrack_Enable_IMM6_13 "绝缘采样使能位_IMM6";
CM_ SG_ 2332108445 M2I_Byrack_ReVeEnable_IMM6_13 "读取软件版本使能位_IMM6";
CM_ SG_ 2332108445 Reserved_13 "预留预留";
CM_ SG_ 2332108445 M2I_Byrack_IsPostTm_IMM6_13 "绝缘采样时间_IMM6";
CM_ SG_ 2332108445 M2I_Byrack_SysABStTm_IMM6_13 "电压稳定时间_IMM6";
CM_ SG_ 2332108446 CRC_M2I_Byrack_IMM6_14 "CRC校验_IMM6";
CM_ SG_ 2332108446 M2I_Byrack_HVS_IMM6_14 "绝缘测量电压_IMM6";
CM_ SG_ 2332108446 M2I_Byrack_Enable_IMM6_14 "绝缘采样使能位_IMM6";
CM_ SG_ 2332108446 M2I_Byrack_ReVeEnable_IMM6_14 "读取软件版本使能位_IMM6";
CM_ SG_ 2332108446 Reserved_14 "预留预留";
CM_ SG_ 2332108446 M2I_Byrack_IsPostTm_IMM6_14 "绝缘采样时间_IMM6";
CM_ SG_ 2332108446 M2I_Byrack_SysABStTm_IMM6_14 "电压稳定时间_IMM6";
CM_ SG_ 2332108447 CRC_M2I_Byrack_IMM6_15 "CRC校验_IMM6";
CM_ SG_ 2332108447 M2I_Byrack_HVS_IMM6_15 "绝缘测量电压_IMM6";
CM_ SG_ 2332108447 M2I_Byrack_Enable_IMM6_15 "绝缘采样使能位_IMM6";
CM_ SG_ 2332108447 M2I_Byrack_ReVeEnable_IMM6_15 "读取软件版本使能位_IMM6";
CM_ SG_ 2332108447 Reserved_15 "预留预留";
CM_ SG_ 2332108447 M2I_Byrack_IsPostTm_IMM6_15 "绝缘采样时间_IMM6";
CM_ SG_ 2332108447 M2I_Byrack_SysABStTm_IMM6_15 "电压稳定时间_IMM6";
CM_ SG_ 2332108448 CRC_M2I_Byrack_IMM6_16 "CRC校验_IMM6";
CM_ SG_ 2332108448 M2I_Byrack_HVS_IMM6_16 "绝缘测量电压_IMM6";
CM_ SG_ 2332108448 M2I_Byrack_Enable_IMM6_16 "绝缘采样使能位_IMM6";
CM_ SG_ 2332108448 M2I_Byrack_ReVeEnable_IMM6_16 "读取软件版本使能位_IMM6";
CM_ SG_ 2332108448 Reserved_16 "预留预留";
CM_ SG_ 2332108448 M2I_Byrack_IsPostTm_IMM6_16 "绝缘采样时间_IMM6";
CM_ SG_ 2332108448 M2I_Byrack_SysABStTm_IMM6_16 "电压稳定时间_IMM6";
CM_ SG_ 2332108449 CRC_M2I_Byrack_IMM6_17 "CRC校验_IMM6";
CM_ SG_ 2332108449 M2I_Byrack_HVS_IMM6_17 "绝缘测量电压_IMM6";
CM_ SG_ 2332108449 M2I_Byrack_Enable_IMM6_17 "绝缘采样使能位_IMM6";
CM_ SG_ 2332108449 M2I_Byrack_ReVeEnable_IMM6_17 "读取软件版本使能位_IMM6";
CM_ SG_ 2332108449 Reserved_17 "预留预留";
CM_ SG_ 2332108449 M2I_Byrack_IsPostTm_IMM6_17 "绝缘采样时间_IMM6";
CM_ SG_ 2332108449 M2I_Byrack_SysABStTm_IMM6_17 "电压稳定时间_IMM6";
CM_ SG_ 2332108450 CRC_M2I_Byrack_IMM6_18 "CRC校验_IMM6";
CM_ SG_ 2332108450 M2I_Byrack_HVS_IMM6_18 "绝缘测量电压_IMM6";
CM_ SG_ 2332108450 M2I_Byrack_Enable_IMM6_18 "绝缘采样使能位_IMM6";
CM_ SG_ 2332108450 M2I_Byrack_ReVeEnable_IMM6_18 "读取软件版本使能位_IMM6";
CM_ SG_ 2332108450 Reserved_18 "预留预留";
CM_ SG_ 2332108450 M2I_Byrack_IsPostTm_IMM6_18 "绝缘采样时间_IMM6";
CM_ SG_ 2332108450 M2I_Byrack_SysABStTm_IMM6_18 "电压稳定时间_IMM6";
CM_ SG_ 2332108451 CRC_M2I_Byrack_IMM6_19 "CRC校验_IMM6";
CM_ SG_ 2332108451 M2I_Byrack_HVS_IMM6_19 "绝缘测量电压_IMM6";
CM_ SG_ 2332108451 M2I_Byrack_Enable_IMM6_19 "绝缘采样使能位_IMM6";
CM_ SG_ 2332108451 M2I_Byrack_ReVeEnable_IMM6_19 "读取软件版本使能位_IMM6";
CM_ SG_ 2332108451 Reserved_19 "预留预留";
CM_ SG_ 2332108451 M2I_Byrack_IsPostTm_IMM6_19 "绝缘采样时间_IMM6";
CM_ SG_ 2332108451 M2I_Byrack_SysABStTm_IMM6_19 "电压稳定时间_IMM6";
CM_ SG_ 2332108452 CRC_M2I_Byrack_IMM6_20 "CRC校验_IMM6";
CM_ SG_ 2332108452 M2I_Byrack_HVS_IMM6_20 "绝缘测量电压_IMM6";
CM_ SG_ 2332108452 M2I_Byrack_Enable_IMM6_20 "绝缘采样使能位_IMM6";
CM_ SG_ 2332108452 M2I_Byrack_ReVeEnable_IMM6_20 "读取软件版本使能位_IMM6";
CM_ SG_ 2332108452 Reserved_20 "预留预留";
CM_ SG_ 2332108452 M2I_Byrack_IsPostTm_IMM6_20 "绝缘采样时间_IMM6";
CM_ SG_ 2332108452 M2I_Byrack_SysABStTm_IMM6_20 "电压稳定时间_IMM6";
CM_ SG_ 2332108453 CRC_M2I_Byrack_IMM6_21 "CRC校验_IMM6";
CM_ SG_ 2332108453 M2I_Byrack_HVS_IMM6_21 "绝缘测量电压_IMM6";
CM_ SG_ 2332108453 M2I_Byrack_Enable_IMM6_21 "绝缘采样使能位_IMM6";
CM_ SG_ 2332108453 M2I_Byrack_ReVeEnable_IMM6_21 "读取软件版本使能位_IMM6";
CM_ SG_ 2332108453 Reserved_21 "预留预留";
CM_ SG_ 2332108453 M2I_Byrack_IsPostTm_IMM6_21 "绝缘采样时间_IMM6";
CM_ SG_ 2332108453 M2I_Byrack_SysABStTm_IMM6_21 "电压稳定时间_IMM6";
CM_ SG_ 2332108454 CRC_M2I_Byrack_IMM6_22 "CRC校验_IMM6";
CM_ SG_ 2332108454 M2I_Byrack_HVS_IMM6_22 "绝缘测量电压_IMM6";
CM_ SG_ 2332108454 M2I_Byrack_Enable_IMM6_22 "绝缘采样使能位_IMM6";
CM_ SG_ 2332108454 M2I_Byrack_ReVeEnable_IMM6_22 "读取软件版本使能位_IMM6";
CM_ SG_ 2332108454 Reserved_22 "预留预留";
CM_ SG_ 2332108454 M2I_Byrack_IsPostTm_IMM6_22 "绝缘采样时间_IMM6";
CM_ SG_ 2332108454 M2I_Byrack_SysABStTm_IMM6_22 "电压稳定时间_IMM6";
CM_ SG_ 2332108455 CRC_M2I_Byrack_IMM6_23 "CRC校验_IMM6";
CM_ SG_ 2332108455 M2I_Byrack_HVS_IMM6_23 "绝缘测量电压_IMM6";
CM_ SG_ 2332108455 M2I_Byrack_Enable_IMM6_23 "绝缘采样使能位_IMM6";
CM_ SG_ 2332108455 M2I_Byrack_ReVeEnable_IMM6_23 "读取软件版本使能位_IMM6";
CM_ SG_ 2332108455 Reserved_23 "预留预留";
CM_ SG_ 2332108455 M2I_Byrack_IsPostTm_IMM6_23 "绝缘采样时间_IMM6";
CM_ SG_ 2332108455 M2I_Byrack_SysABStTm_IMM6_23 "电压稳定时间_IMM6";
CM_ SG_ 2332108456 CRC_M2I_Byrack_IMM6_24 "CRC校验_IMM6";
CM_ SG_ 2332108456 M2I_Byrack_HVS_IMM6_24 "绝缘测量电压_IMM6";
CM_ SG_ 2332108456 M2I_Byrack_Enable_IMM6_24 "绝缘采样使能位_IMM6";
CM_ SG_ 2332108456 M2I_Byrack_ReVeEnable_IMM6_24 "读取软件版本使能位_IMM6";
CM_ SG_ 2332108456 Reserved_24 "预留预留";
CM_ SG_ 2332108456 M2I_Byrack_IsPostTm_IMM6_24 "绝缘采样时间_IMM6";
CM_ SG_ 2332108456 M2I_Byrack_SysABStTm_IMM6_24 "电压稳定时间_IMM6";
CM_ SG_ 2332108457 CRC_M2I_Byrack_IMM6_25 "CRC校验_IMM6";
CM_ SG_ 2332108457 M2I_Byrack_HVS_IMM6_25 "绝缘测量电压_IMM6";
CM_ SG_ 2332108457 M2I_Byrack_Enable_IMM6_25 "绝缘采样使能位_IMM6";
CM_ SG_ 2332108457 M2I_Byrack_ReVeEnable_IMM6_25 "读取软件版本使能位_IMM6";
CM_ SG_ 2332108457 Reserved_25 "预留预留";
CM_ SG_ 2332108457 M2I_Byrack_IsPostTm_IMM6_25 "绝缘采样时间_IMM6";
CM_ SG_ 2332108457 M2I_Byrack_SysABStTm_IMM6_25 "电压稳定时间_IMM6";
CM_ SG_ 2332108458 CRC_M2I_Byrack_IMM6_26 "CRC校验_IMM6";
CM_ SG_ 2332108458 M2I_Byrack_HVS_IMM6_26 "绝缘测量电压_IMM6";
CM_ SG_ 2332108458 M2I_Byrack_Enable_IMM6_26 "绝缘采样使能位_IMM6";
CM_ SG_ 2332108458 M2I_Byrack_ReVeEnable_IMM6_26 "读取软件版本使能位_IMM6";
CM_ SG_ 2332108458 Reserved_26 "预留预留";
CM_ SG_ 2332108458 M2I_Byrack_IsPostTm_IMM6_26 "绝缘采样时间_IMM6";
CM_ SG_ 2332108458 M2I_Byrack_SysABStTm_IMM6_26 "电压稳定时间_IMM6";
CM_ SG_ 2332108459 CRC_M2I_Byrack_IMM6_27 "CRC校验_IMM6";
CM_ SG_ 2332108459 M2I_Byrack_HVS_IMM6_27 "绝缘测量电压_IMM6";
CM_ SG_ 2332108459 M2I_Byrack_Enable_IMM6_27 "绝缘采样使能位_IMM6";
CM_ SG_ 2332108459 M2I_Byrack_ReVeEnable_IMM6_27 "读取软件版本使能位_IMM6";
CM_ SG_ 2332108459 Reserved_27 "预留预留";
CM_ SG_ 2332108459 M2I_Byrack_IsPostTm_IMM6_27 "绝缘采样时间_IMM6";
CM_ SG_ 2332108459 M2I_Byrack_SysABStTm_IMM6_27 "电压稳定时间_IMM6";
CM_ SG_ 2332108460 CRC_M2I_Byrack_IMM6_28 "CRC校验_IMM6";
CM_ SG_ 2332108460 M2I_Byrack_HVS_IMM6_28 "绝缘测量电压_IMM6";
CM_ SG_ 2332108460 M2I_Byrack_Enable_IMM6_28 "绝缘采样使能位_IMM6";
CM_ SG_ 2332108460 M2I_Byrack_ReVeEnable_IMM6_28 "读取软件版本使能位_IMM6";
CM_ SG_ 2332108460 Reserved_28 "预留预留";
CM_ SG_ 2332108460 M2I_Byrack_IsPostTm_IMM6_28 "绝缘采样时间_IMM6";
CM_ SG_ 2332108460 M2I_Byrack_SysABStTm_IMM6_28 "电压稳定时间_IMM6";
CM_ SG_ 2332108461 CRC_M2I_Byrack_IMM6_29 "CRC校验_IMM6";
CM_ SG_ 2332108461 M2I_Byrack_HVS_IMM6_29 "绝缘测量电压_IMM6";
CM_ SG_ 2332108461 M2I_Byrack_Enable_IMM6_29 "绝缘采样使能位_IMM6";
CM_ SG_ 2332108461 M2I_Byrack_ReVeEnable_IMM6_29 "读取软件版本使能位_IMM6";
CM_ SG_ 2332108461 Reserved_29 "预留预留";
CM_ SG_ 2332108461 M2I_Byrack_IsPostTm_IMM6_29 "绝缘采样时间_IMM6";
CM_ SG_ 2332108461 M2I_Byrack_SysABStTm_IMM6_29 "电压稳定时间_IMM6";
CM_ SG_ 2332108462 CRC_M2I_Byrack_IMM6_30 "CRC校验_IMM6";
CM_ SG_ 2332108462 M2I_Byrack_HVS_IMM6_30 "绝缘测量电压_IMM6";
CM_ SG_ 2332108462 M2I_Byrack_Enable_IMM6_30 "绝缘采样使能位_IMM6";
CM_ SG_ 2332108462 M2I_Byrack_ReVeEnable_IMM6_30 "读取软件版本使能位_IMM6";
CM_ SG_ 2332108462 Reserved_30 "预留预留";
CM_ SG_ 2332108462 M2I_Byrack_IsPostTm_IMM6_30 "绝缘采样时间_IMM6";
CM_ SG_ 2332108462 M2I_Byrack_SysABStTm_IMM6_30 "电压稳定时间_IMM6";
CM_ SG_ 2332108463 CRC_M2I_Byrack_IMM6_31 "CRC校验_IMM6";
CM_ SG_ 2332108463 M2I_Byrack_HVS_IMM6_31 "绝缘测量电压_IMM6";
CM_ SG_ 2332108463 M2I_Byrack_Enable_IMM6_31 "绝缘采样使能位_IMM6";
CM_ SG_ 2332108463 M2I_Byrack_ReVeEnable_IMM6_31 "读取软件版本使能位_IMM6";
CM_ SG_ 2332108463 Reserved_31 "预留预留";
CM_ SG_ 2332108463 M2I_Byrack_IsPostTm_IMM6_31 "绝缘采样时间_IMM6";
CM_ SG_ 2332108463 M2I_Byrack_SysABStTm_IMM6_31 "电压稳定时间_IMM6";
CM_ SG_ 2332108689 CRC_M2I_Byrack_IMM7_01 "CRC校验_IMM7";
CM_ SG_ 2332108689 M2I_Byrack_HVS_IMM7_01 "绝缘测量电压_IMM7";
CM_ SG_ 2332108689 M2I_Byrack_Enable_IMM7_01 "绝缘采样使能位_IMM7";
CM_ SG_ 2332108689 M2I_Byrack_ReVeEnable_IMM7_01 "读取软件版本使能位_IMM7";
CM_ SG_ 2332108689 Reserved_01 "预留预留";
CM_ SG_ 2332108689 M2I_Byrack_IsPostTm_IMM7_01 "绝缘采样时间_IMM7";
CM_ SG_ 2332108689 M2I_Byrack_SysABStTm_IMM7_01 "电压稳定时间_IMM7";
CM_ SG_ 2332108690 CRC_M2I_Byrack_IMM7_02 "CRC校验_IMM7";
CM_ SG_ 2332108690 M2I_Byrack_HVS_IMM7_02 "绝缘测量电压_IMM7";
CM_ SG_ 2332108690 M2I_Byrack_Enable_IMM7_02 "绝缘采样使能位_IMM7";
CM_ SG_ 2332108690 M2I_Byrack_ReVeEnable_IMM7_02 "读取软件版本使能位_IMM7";
CM_ SG_ 2332108690 Reserved_02 "预留预留";
CM_ SG_ 2332108690 M2I_Byrack_IsPostTm_IMM7_02 "绝缘采样时间_IMM7";
CM_ SG_ 2332108690 M2I_Byrack_SysABStTm_IMM7_02 "电压稳定时间_IMM7";
CM_ SG_ 2332108691 CRC_M2I_Byrack_IMM7_03 "CRC校验_IMM7";
CM_ SG_ 2332108691 M2I_Byrack_HVS_IMM7_03 "绝缘测量电压_IMM7";
CM_ SG_ 2332108691 M2I_Byrack_Enable_IMM7_03 "绝缘采样使能位_IMM7";
CM_ SG_ 2332108691 M2I_Byrack_ReVeEnable_IMM7_03 "读取软件版本使能位_IMM7";
CM_ SG_ 2332108691 Reserved_03 "预留预留";
CM_ SG_ 2332108691 M2I_Byrack_IsPostTm_IMM7_03 "绝缘采样时间_IMM7";
CM_ SG_ 2332108691 M2I_Byrack_SysABStTm_IMM7_03 "电压稳定时间_IMM7";
CM_ SG_ 2332108692 CRC_M2I_Byrack_IMM7_04 "CRC校验_IMM7";
CM_ SG_ 2332108692 M2I_Byrack_HVS_IMM7_04 "绝缘测量电压_IMM7";
CM_ SG_ 2332108692 M2I_Byrack_Enable_IMM7_04 "绝缘采样使能位_IMM7";
CM_ SG_ 2332108692 M2I_Byrack_ReVeEnable_IMM7_04 "读取软件版本使能位_IMM7";
CM_ SG_ 2332108692 Reserved_04 "预留预留";
CM_ SG_ 2332108692 M2I_Byrack_IsPostTm_IMM7_04 "绝缘采样时间_IMM7";
CM_ SG_ 2332108692 M2I_Byrack_SysABStTm_IMM7_04 "电压稳定时间_IMM7";
CM_ SG_ 2332108693 CRC_M2I_Byrack_IMM7_05 "CRC校验_IMM7";
CM_ SG_ 2332108693 M2I_Byrack_HVS_IMM7_05 "绝缘测量电压_IMM7";
CM_ SG_ 2332108693 M2I_Byrack_Enable_IMM7_05 "绝缘采样使能位_IMM7";
CM_ SG_ 2332108693 M2I_Byrack_ReVeEnable_IMM7_05 "读取软件版本使能位_IMM7";
CM_ SG_ 2332108693 Reserved_05 "预留预留";
CM_ SG_ 2332108693 M2I_Byrack_IsPostTm_IMM7_05 "绝缘采样时间_IMM7";
CM_ SG_ 2332108693 M2I_Byrack_SysABStTm_IMM7_05 "电压稳定时间_IMM7";
CM_ SG_ 2332108694 CRC_M2I_Byrack_IMM7_06 "CRC校验_IMM7";
CM_ SG_ 2332108694 M2I_Byrack_HVS_IMM7_06 "绝缘测量电压_IMM7";
CM_ SG_ 2332108694 M2I_Byrack_Enable_IMM7_06 "绝缘采样使能位_IMM7";
CM_ SG_ 2332108694 M2I_Byrack_ReVeEnable_IMM7_06 "读取软件版本使能位_IMM7";
CM_ SG_ 2332108694 Reserved_06 "预留预留";
CM_ SG_ 2332108694 M2I_Byrack_IsPostTm_IMM7_06 "绝缘采样时间_IMM7";
CM_ SG_ 2332108694 M2I_Byrack_SysABStTm_IMM7_06 "电压稳定时间_IMM7";
CM_ SG_ 2332108695 CRC_M2I_Byrack_IMM7_07 "CRC校验_IMM7";
CM_ SG_ 2332108695 M2I_Byrack_HVS_IMM7_07 "绝缘测量电压_IMM7";
CM_ SG_ 2332108695 M2I_Byrack_Enable_IMM7_07 "绝缘采样使能位_IMM7";
CM_ SG_ 2332108695 M2I_Byrack_ReVeEnable_IMM7_07 "读取软件版本使能位_IMM7";
CM_ SG_ 2332108695 Reserved_07 "预留预留";
CM_ SG_ 2332108695 M2I_Byrack_IsPostTm_IMM7_07 "绝缘采样时间_IMM7";
CM_ SG_ 2332108695 M2I_Byrack_SysABStTm_IMM7_07 "电压稳定时间_IMM7";
CM_ SG_ 2332108696 CRC_M2I_Byrack_IMM7_08 "CRC校验_IMM7";
CM_ SG_ 2332108696 M2I_Byrack_HVS_IMM7_08 "绝缘测量电压_IMM7";
CM_ SG_ 2332108696 M2I_Byrack_Enable_IMM7_08 "绝缘采样使能位_IMM7";
CM_ SG_ 2332108696 M2I_Byrack_ReVeEnable_IMM7_08 "读取软件版本使能位_IMM7";
CM_ SG_ 2332108696 Reserved_08 "预留预留";
CM_ SG_ 2332108696 M2I_Byrack_IsPostTm_IMM7_08 "绝缘采样时间_IMM7";
CM_ SG_ 2332108696 M2I_Byrack_SysABStTm_IMM7_08 "电压稳定时间_IMM7";
CM_ SG_ 2332108697 CRC_M2I_Byrack_IMM7_09 "CRC校验_IMM7";
CM_ SG_ 2332108697 M2I_Byrack_HVS_IMM7_09 "绝缘测量电压_IMM7";
CM_ SG_ 2332108697 M2I_Byrack_Enable_IMM7_09 "绝缘采样使能位_IMM7";
CM_ SG_ 2332108697 M2I_Byrack_ReVeEnable_IMM7_09 "读取软件版本使能位_IMM7";
CM_ SG_ 2332108697 Reserved_09 "预留预留";
CM_ SG_ 2332108697 M2I_Byrack_IsPostTm_IMM7_09 "绝缘采样时间_IMM7";
CM_ SG_ 2332108697 M2I_Byrack_SysABStTm_IMM7_09 "电压稳定时间_IMM7";
CM_ SG_ 2332108698 CRC_M2I_Byrack_IMM7_10 "CRC校验_IMM7";
CM_ SG_ 2332108698 M2I_Byrack_HVS_IMM7_10 "绝缘测量电压_IMM7";
CM_ SG_ 2332108698 M2I_Byrack_Enable_IMM7_10 "绝缘采样使能位_IMM7";
CM_ SG_ 2332108698 M2I_Byrack_ReVeEnable_IMM7_10 "读取软件版本使能位_IMM7";
CM_ SG_ 2332108698 Reserved_10 "预留预留";
CM_ SG_ 2332108698 M2I_Byrack_IsPostTm_IMM7_10 "绝缘采样时间_IMM7";
CM_ SG_ 2332108698 M2I_Byrack_SysABStTm_IMM7_10 "电压稳定时间_IMM7";
CM_ SG_ 2332108699 CRC_M2I_Byrack_IMM7_11 "CRC校验_IMM7";
CM_ SG_ 2332108699 M2I_Byrack_HVS_IMM7_11 "绝缘测量电压_IMM7";
CM_ SG_ 2332108699 M2I_Byrack_Enable_IMM7_11 "绝缘采样使能位_IMM7";
CM_ SG_ 2332108699 M2I_Byrack_ReVeEnable_IMM7_11 "读取软件版本使能位_IMM7";
CM_ SG_ 2332108699 Reserved_11 "预留预留";
CM_ SG_ 2332108699 M2I_Byrack_IsPostTm_IMM7_11 "绝缘采样时间_IMM7";
CM_ SG_ 2332108699 M2I_Byrack_SysABStTm_IMM7_11 "电压稳定时间_IMM7";
CM_ SG_ 2332108700 CRC_M2I_Byrack_IMM7_12 "CRC校验_IMM7";
CM_ SG_ 2332108700 M2I_Byrack_HVS_IMM7_12 "绝缘测量电压_IMM7";
CM_ SG_ 2332108700 M2I_Byrack_Enable_IMM7_12 "绝缘采样使能位_IMM7";
CM_ SG_ 2332108700 M2I_Byrack_ReVeEnable_IMM7_12 "读取软件版本使能位_IMM7";
CM_ SG_ 2332108700 Reserved_12 "预留预留";
CM_ SG_ 2332108700 M2I_Byrack_IsPostTm_IMM7_12 "绝缘采样时间_IMM7";
CM_ SG_ 2332108700 M2I_Byrack_SysABStTm_IMM7_12 "电压稳定时间_IMM7";
CM_ SG_ 2332108701 CRC_M2I_Byrack_IMM7_13 "CRC校验_IMM7";
CM_ SG_ 2332108701 M2I_Byrack_HVS_IMM7_13 "绝缘测量电压_IMM7";
CM_ SG_ 2332108701 M2I_Byrack_Enable_IMM7_13 "绝缘采样使能位_IMM7";
CM_ SG_ 2332108701 M2I_Byrack_ReVeEnable_IMM7_13 "读取软件版本使能位_IMM7";
CM_ SG_ 2332108701 Reserved_13 "预留预留";
CM_ SG_ 2332108701 M2I_Byrack_IsPostTm_IMM7_13 "绝缘采样时间_IMM7";
CM_ SG_ 2332108701 M2I_Byrack_SysABStTm_IMM7_13 "电压稳定时间_IMM7";
CM_ SG_ 2332108702 CRC_M2I_Byrack_IMM7_14 "CRC校验_IMM7";
CM_ SG_ 2332108702 M2I_Byrack_HVS_IMM7_14 "绝缘测量电压_IMM7";
CM_ SG_ 2332108702 M2I_Byrack_Enable_IMM7_14 "绝缘采样使能位_IMM7";
CM_ SG_ 2332108702 M2I_Byrack_ReVeEnable_IMM7_14 "读取软件版本使能位_IMM7";
CM_ SG_ 2332108702 Reserved_14 "预留预留";
CM_ SG_ 2332108702 M2I_Byrack_IsPostTm_IMM7_14 "绝缘采样时间_IMM7";
CM_ SG_ 2332108702 M2I_Byrack_SysABStTm_IMM7_14 "电压稳定时间_IMM7";
CM_ SG_ 2332108703 CRC_M2I_Byrack_IMM7_15 "CRC校验_IMM7";
CM_ SG_ 2332108703 M2I_Byrack_HVS_IMM7_15 "绝缘测量电压_IMM7";
CM_ SG_ 2332108703 M2I_Byrack_Enable_IMM7_15 "绝缘采样使能位_IMM7";
CM_ SG_ 2332108703 M2I_Byrack_ReVeEnable_IMM7_15 "读取软件版本使能位_IMM7";
CM_ SG_ 2332108703 Reserved_15 "预留预留";
CM_ SG_ 2332108703 M2I_Byrack_IsPostTm_IMM7_15 "绝缘采样时间_IMM7";
CM_ SG_ 2332108703 M2I_Byrack_SysABStTm_IMM7_15 "电压稳定时间_IMM7";
CM_ SG_ 2332108704 CRC_M2I_Byrack_IMM7_16 "CRC校验_IMM7";
CM_ SG_ 2332108704 M2I_Byrack_HVS_IMM7_16 "绝缘测量电压_IMM7";
CM_ SG_ 2332108704 M2I_Byrack_Enable_IMM7_16 "绝缘采样使能位_IMM7";
CM_ SG_ 2332108704 M2I_Byrack_ReVeEnable_IMM7_16 "读取软件版本使能位_IMM7";
CM_ SG_ 2332108704 Reserved_16 "预留预留";
CM_ SG_ 2332108704 M2I_Byrack_IsPostTm_IMM7_16 "绝缘采样时间_IMM7";
CM_ SG_ 2332108704 M2I_Byrack_SysABStTm_IMM7_16 "电压稳定时间_IMM7";
CM_ SG_ 2332108705 CRC_M2I_Byrack_IMM7_17 "CRC校验_IMM7";
CM_ SG_ 2332108705 M2I_Byrack_HVS_IMM7_17 "绝缘测量电压_IMM7";
CM_ SG_ 2332108705 M2I_Byrack_Enable_IMM7_17 "绝缘采样使能位_IMM7";
CM_ SG_ 2332108705 M2I_Byrack_ReVeEnable_IMM7_17 "读取软件版本使能位_IMM7";
CM_ SG_ 2332108705 Reserved_17 "预留预留";
CM_ SG_ 2332108705 M2I_Byrack_IsPostTm_IMM7_17 "绝缘采样时间_IMM7";
CM_ SG_ 2332108705 M2I_Byrack_SysABStTm_IMM7_17 "电压稳定时间_IMM7";
CM_ SG_ 2332108706 CRC_M2I_Byrack_IMM7_18 "CRC校验_IMM7";
CM_ SG_ 2332108706 M2I_Byrack_HVS_IMM7_18 "绝缘测量电压_IMM7";
CM_ SG_ 2332108706 M2I_Byrack_Enable_IMM7_18 "绝缘采样使能位_IMM7";
CM_ SG_ 2332108706 M2I_Byrack_ReVeEnable_IMM7_18 "读取软件版本使能位_IMM7";
CM_ SG_ 2332108706 Reserved_18 "预留预留";
CM_ SG_ 2332108706 M2I_Byrack_IsPostTm_IMM7_18 "绝缘采样时间_IMM7";
CM_ SG_ 2332108706 M2I_Byrack_SysABStTm_IMM7_18 "电压稳定时间_IMM7";
CM_ SG_ 2332108707 CRC_M2I_Byrack_IMM7_19 "CRC校验_IMM7";
CM_ SG_ 2332108707 M2I_Byrack_HVS_IMM7_19 "绝缘测量电压_IMM7";
CM_ SG_ 2332108707 M2I_Byrack_Enable_IMM7_19 "绝缘采样使能位_IMM7";
CM_ SG_ 2332108707 M2I_Byrack_ReVeEnable_IMM7_19 "读取软件版本使能位_IMM7";
CM_ SG_ 2332108707 Reserved_19 "预留预留";
CM_ SG_ 2332108707 M2I_Byrack_IsPostTm_IMM7_19 "绝缘采样时间_IMM7";
CM_ SG_ 2332108707 M2I_Byrack_SysABStTm_IMM7_19 "电压稳定时间_IMM7";
CM_ SG_ 2332108708 CRC_M2I_Byrack_IMM7_20 "CRC校验_IMM7";
CM_ SG_ 2332108708 M2I_Byrack_HVS_IMM7_20 "绝缘测量电压_IMM7";
CM_ SG_ 2332108708 M2I_Byrack_Enable_IMM7_20 "绝缘采样使能位_IMM7";
CM_ SG_ 2332108708 M2I_Byrack_ReVeEnable_IMM7_20 "读取软件版本使能位_IMM7";
CM_ SG_ 2332108708 Reserved_20 "预留预留";
CM_ SG_ 2332108708 M2I_Byrack_IsPostTm_IMM7_20 "绝缘采样时间_IMM7";
CM_ SG_ 2332108708 M2I_Byrack_SysABStTm_IMM7_20 "电压稳定时间_IMM7";
CM_ SG_ 2332108709 CRC_M2I_Byrack_IMM7_21 "CRC校验_IMM7";
CM_ SG_ 2332108709 M2I_Byrack_HVS_IMM7_21 "绝缘测量电压_IMM7";
CM_ SG_ 2332108709 M2I_Byrack_Enable_IMM7_21 "绝缘采样使能位_IMM7";
CM_ SG_ 2332108709 M2I_Byrack_ReVeEnable_IMM7_21 "读取软件版本使能位_IMM7";
CM_ SG_ 2332108709 Reserved_21 "预留预留";
CM_ SG_ 2332108709 M2I_Byrack_IsPostTm_IMM7_21 "绝缘采样时间_IMM7";
CM_ SG_ 2332108709 M2I_Byrack_SysABStTm_IMM7_21 "电压稳定时间_IMM7";
CM_ SG_ 2332108710 CRC_M2I_Byrack_IMM7_22 "CRC校验_IMM7";
CM_ SG_ 2332108710 M2I_Byrack_HVS_IMM7_22 "绝缘测量电压_IMM7";
CM_ SG_ 2332108710 M2I_Byrack_Enable_IMM7_22 "绝缘采样使能位_IMM7";
CM_ SG_ 2332108710 M2I_Byrack_ReVeEnable_IMM7_22 "读取软件版本使能位_IMM7";
CM_ SG_ 2332108710 Reserved_22 "预留预留";
CM_ SG_ 2332108710 M2I_Byrack_IsPostTm_IMM7_22 "绝缘采样时间_IMM7";
CM_ SG_ 2332108710 M2I_Byrack_SysABStTm_IMM7_22 "电压稳定时间_IMM7";
CM_ SG_ 2332108711 CRC_M2I_Byrack_IMM7_23 "CRC校验_IMM7";
CM_ SG_ 2332108711 M2I_Byrack_HVS_IMM7_23 "绝缘测量电压_IMM7";
CM_ SG_ 2332108711 M2I_Byrack_Enable_IMM7_23 "绝缘采样使能位_IMM7";
CM_ SG_ 2332108711 M2I_Byrack_ReVeEnable_IMM7_23 "读取软件版本使能位_IMM7";
CM_ SG_ 2332108711 Reserved_23 "预留预留";
CM_ SG_ 2332108711 M2I_Byrack_IsPostTm_IMM7_23 "绝缘采样时间_IMM7";
CM_ SG_ 2332108711 M2I_Byrack_SysABStTm_IMM7_23 "电压稳定时间_IMM7";
CM_ SG_ 2332108712 CRC_M2I_Byrack_IMM7_24 "CRC校验_IMM7";
CM_ SG_ 2332108712 M2I_Byrack_HVS_IMM7_24 "绝缘测量电压_IMM7";
CM_ SG_ 2332108712 M2I_Byrack_Enable_IMM7_24 "绝缘采样使能位_IMM7";
CM_ SG_ 2332108712 M2I_Byrack_ReVeEnable_IMM7_24 "读取软件版本使能位_IMM7";
CM_ SG_ 2332108712 Reserved_24 "预留预留";
CM_ SG_ 2332108712 M2I_Byrack_IsPostTm_IMM7_24 "绝缘采样时间_IMM7";
CM_ SG_ 2332108712 M2I_Byrack_SysABStTm_IMM7_24 "电压稳定时间_IMM7";
CM_ SG_ 2332108713 CRC_M2I_Byrack_IMM7_25 "CRC校验_IMM7";
CM_ SG_ 2332108713 M2I_Byrack_HVS_IMM7_25 "绝缘测量电压_IMM7";
CM_ SG_ 2332108713 M2I_Byrack_Enable_IMM7_25 "绝缘采样使能位_IMM7";
CM_ SG_ 2332108713 M2I_Byrack_ReVeEnable_IMM7_25 "读取软件版本使能位_IMM7";
CM_ SG_ 2332108713 Reserved_25 "预留预留";
CM_ SG_ 2332108713 M2I_Byrack_IsPostTm_IMM7_25 "绝缘采样时间_IMM7";
CM_ SG_ 2332108713 M2I_Byrack_SysABStTm_IMM7_25 "电压稳定时间_IMM7";
CM_ SG_ 2332108714 CRC_M2I_Byrack_IMM7_26 "CRC校验_IMM7";
CM_ SG_ 2332108714 M2I_Byrack_HVS_IMM7_26 "绝缘测量电压_IMM7";
CM_ SG_ 2332108714 M2I_Byrack_Enable_IMM7_26 "绝缘采样使能位_IMM7";
CM_ SG_ 2332108714 M2I_Byrack_ReVeEnable_IMM7_26 "读取软件版本使能位_IMM7";
CM_ SG_ 2332108714 Reserved_26 "预留预留";
CM_ SG_ 2332108714 M2I_Byrack_IsPostTm_IMM7_26 "绝缘采样时间_IMM7";
CM_ SG_ 2332108714 M2I_Byrack_SysABStTm_IMM7_26 "电压稳定时间_IMM7";
CM_ SG_ 2332108715 CRC_M2I_Byrack_IMM7_27 "CRC校验_IMM7";
CM_ SG_ 2332108715 M2I_Byrack_HVS_IMM7_27 "绝缘测量电压_IMM7";
CM_ SG_ 2332108715 M2I_Byrack_Enable_IMM7_27 "绝缘采样使能位_IMM7";
CM_ SG_ 2332108715 M2I_Byrack_ReVeEnable_IMM7_27 "读取软件版本使能位_IMM7";
CM_ SG_ 2332108715 Reserved_27 "预留预留";
CM_ SG_ 2332108715 M2I_Byrack_IsPostTm_IMM7_27 "绝缘采样时间_IMM7";
CM_ SG_ 2332108715 M2I_Byrack_SysABStTm_IMM7_27 "电压稳定时间_IMM7";
CM_ SG_ 2332108716 CRC_M2I_Byrack_IMM7_28 "CRC校验_IMM7";
CM_ SG_ 2332108716 M2I_Byrack_HVS_IMM7_28 "绝缘测量电压_IMM7";
CM_ SG_ 2332108716 M2I_Byrack_Enable_IMM7_28 "绝缘采样使能位_IMM7";
CM_ SG_ 2332108716 M2I_Byrack_ReVeEnable_IMM7_28 "读取软件版本使能位_IMM7";
CM_ SG_ 2332108716 Reserved_28 "预留预留";
CM_ SG_ 2332108716 M2I_Byrack_IsPostTm_IMM7_28 "绝缘采样时间_IMM7";
CM_ SG_ 2332108716 M2I_Byrack_SysABStTm_IMM7_28 "电压稳定时间_IMM7";
CM_ SG_ 2332108717 CRC_M2I_Byrack_IMM7_29 "CRC校验_IMM7";
CM_ SG_ 2332108717 M2I_Byrack_HVS_IMM7_29 "绝缘测量电压_IMM7";
CM_ SG_ 2332108717 M2I_Byrack_Enable_IMM7_29 "绝缘采样使能位_IMM7";
CM_ SG_ 2332108717 M2I_Byrack_ReVeEnable_IMM7_29 "读取软件版本使能位_IMM7";
CM_ SG_ 2332108717 Reserved_29 "预留预留";
CM_ SG_ 2332108717 M2I_Byrack_IsPostTm_IMM7_29 "绝缘采样时间_IMM7";
CM_ SG_ 2332108717 M2I_Byrack_SysABStTm_IMM7_29 "电压稳定时间_IMM7";
CM_ SG_ 2332108718 CRC_M2I_Byrack_IMM7_30 "CRC校验_IMM7";
CM_ SG_ 2332108718 M2I_Byrack_HVS_IMM7_30 "绝缘测量电压_IMM7";
CM_ SG_ 2332108718 M2I_Byrack_Enable_IMM7_30 "绝缘采样使能位_IMM7";
CM_ SG_ 2332108718 M2I_Byrack_ReVeEnable_IMM7_30 "读取软件版本使能位_IMM7";
CM_ SG_ 2332108718 Reserved_30 "预留预留";
CM_ SG_ 2332108718 M2I_Byrack_IsPostTm_IMM7_30 "绝缘采样时间_IMM7";
CM_ SG_ 2332108718 M2I_Byrack_SysABStTm_IMM7_30 "电压稳定时间_IMM7";
CM_ SG_ 2332108719 CRC_M2I_Byrack_IMM7_31 "CRC校验_IMM7";
CM_ SG_ 2332108719 M2I_Byrack_HVS_IMM7_31 "绝缘测量电压_IMM7";
CM_ SG_ 2332108719 M2I_Byrack_Enable_IMM7_31 "绝缘采样使能位_IMM7";
CM_ SG_ 2332108719 M2I_Byrack_ReVeEnable_IMM7_31 "读取软件版本使能位_IMM7";
CM_ SG_ 2332108719 Reserved_31 "预留预留";
CM_ SG_ 2332108719 M2I_Byrack_IsPostTm_IMM7_31 "绝缘采样时间_IMM7";
CM_ SG_ 2332108719 M2I_Byrack_SysABStTm_IMM7_31 "电压稳定时间_IMM7";
CM_ SG_ 2332108945 CRC_M2I_Byrack_IMM8_01 "CRC校验_IMM8";
CM_ SG_ 2332108945 M2I_Byrack_HVS_IMM8_01 "绝缘测量电压_IMM8";
CM_ SG_ 2332108945 M2I_Byrack_Enable_IMM8_01 "绝缘采样使能位_IMM8";
CM_ SG_ 2332108945 M2I_Byrack_ReVeEnable_IMM8_01 "读取软件版本使能位_IMM8";
CM_ SG_ 2332108945 Reserved_01 "预留预留";
CM_ SG_ 2332108945 M2I_Byrack_IsPostTm_IMM8_01 "绝缘采样时间_IMM8";
CM_ SG_ 2332108945 M2I_Byrack_SysABStTm_IMM8_01 "电压稳定时间_IMM8";
CM_ SG_ 2332108946 CRC_M2I_Byrack_IMM8_02 "CRC校验_IMM8";
CM_ SG_ 2332108946 M2I_Byrack_HVS_IMM8_02 "绝缘测量电压_IMM8";
CM_ SG_ 2332108946 M2I_Byrack_Enable_IMM8_02 "绝缘采样使能位_IMM8";
CM_ SG_ 2332108946 M2I_Byrack_ReVeEnable_IMM8_02 "读取软件版本使能位_IMM8";
CM_ SG_ 2332108946 Reserved_02 "预留预留";
CM_ SG_ 2332108946 M2I_Byrack_IsPostTm_IMM8_02 "绝缘采样时间_IMM8";
CM_ SG_ 2332108946 M2I_Byrack_SysABStTm_IMM8_02 "电压稳定时间_IMM8";
CM_ SG_ 2332108947 CRC_M2I_Byrack_IMM8_03 "CRC校验_IMM8";
CM_ SG_ 2332108947 M2I_Byrack_HVS_IMM8_03 "绝缘测量电压_IMM8";
CM_ SG_ 2332108947 M2I_Byrack_Enable_IMM8_03 "绝缘采样使能位_IMM8";
CM_ SG_ 2332108947 M2I_Byrack_ReVeEnable_IMM8_03 "读取软件版本使能位_IMM8";
CM_ SG_ 2332108947 Reserved_03 "预留预留";
CM_ SG_ 2332108947 M2I_Byrack_IsPostTm_IMM8_03 "绝缘采样时间_IMM8";
CM_ SG_ 2332108947 M2I_Byrack_SysABStTm_IMM8_03 "电压稳定时间_IMM8";
CM_ SG_ 2332108948 CRC_M2I_Byrack_IMM8_04 "CRC校验_IMM8";
CM_ SG_ 2332108948 M2I_Byrack_HVS_IMM8_04 "绝缘测量电压_IMM8";
CM_ SG_ 2332108948 M2I_Byrack_Enable_IMM8_04 "绝缘采样使能位_IMM8";
CM_ SG_ 2332108948 M2I_Byrack_ReVeEnable_IMM8_04 "读取软件版本使能位_IMM8";
CM_ SG_ 2332108948 Reserved_04 "预留预留";
CM_ SG_ 2332108948 M2I_Byrack_IsPostTm_IMM8_04 "绝缘采样时间_IMM8";
CM_ SG_ 2332108948 M2I_Byrack_SysABStTm_IMM8_04 "电压稳定时间_IMM8";
CM_ SG_ 2332108949 CRC_M2I_Byrack_IMM8_05 "CRC校验_IMM8";
CM_ SG_ 2332108949 M2I_Byrack_HVS_IMM8_05 "绝缘测量电压_IMM8";
CM_ SG_ 2332108949 M2I_Byrack_Enable_IMM8_05 "绝缘采样使能位_IMM8";
CM_ SG_ 2332108949 M2I_Byrack_ReVeEnable_IMM8_05 "读取软件版本使能位_IMM8";
CM_ SG_ 2332108949 Reserved_05 "预留预留";
CM_ SG_ 2332108949 M2I_Byrack_IsPostTm_IMM8_05 "绝缘采样时间_IMM8";
CM_ SG_ 2332108949 M2I_Byrack_SysABStTm_IMM8_05 "电压稳定时间_IMM8";
CM_ SG_ 2332108950 CRC_M2I_Byrack_IMM8_06 "CRC校验_IMM8";
CM_ SG_ 2332108950 M2I_Byrack_HVS_IMM8_06 "绝缘测量电压_IMM8";
CM_ SG_ 2332108950 M2I_Byrack_Enable_IMM8_06 "绝缘采样使能位_IMM8";
CM_ SG_ 2332108950 M2I_Byrack_ReVeEnable_IMM8_06 "读取软件版本使能位_IMM8";
CM_ SG_ 2332108950 Reserved_06 "预留预留";
CM_ SG_ 2332108950 M2I_Byrack_IsPostTm_IMM8_06 "绝缘采样时间_IMM8";
CM_ SG_ 2332108950 M2I_Byrack_SysABStTm_IMM8_06 "电压稳定时间_IMM8";
CM_ SG_ 2332108951 CRC_M2I_Byrack_IMM8_07 "CRC校验_IMM8";
CM_ SG_ 2332108951 M2I_Byrack_HVS_IMM8_07 "绝缘测量电压_IMM8";
CM_ SG_ 2332108951 M2I_Byrack_Enable_IMM8_07 "绝缘采样使能位_IMM8";
CM_ SG_ 2332108951 M2I_Byrack_ReVeEnable_IMM8_07 "读取软件版本使能位_IMM8";
CM_ SG_ 2332108951 Reserved_07 "预留预留";
CM_ SG_ 2332108951 M2I_Byrack_IsPostTm_IMM8_07 "绝缘采样时间_IMM8";
CM_ SG_ 2332108951 M2I_Byrack_SysABStTm_IMM8_07 "电压稳定时间_IMM8";
CM_ SG_ 2332108952 CRC_M2I_Byrack_IMM8_08 "CRC校验_IMM8";
CM_ SG_ 2332108952 M2I_Byrack_HVS_IMM8_08 "绝缘测量电压_IMM8";
CM_ SG_ 2332108952 M2I_Byrack_Enable_IMM8_08 "绝缘采样使能位_IMM8";
CM_ SG_ 2332108952 M2I_Byrack_ReVeEnable_IMM8_08 "读取软件版本使能位_IMM8";
CM_ SG_ 2332108952 Reserved_08 "预留预留";
CM_ SG_ 2332108952 M2I_Byrack_IsPostTm_IMM8_08 "绝缘采样时间_IMM8";
CM_ SG_ 2332108952 M2I_Byrack_SysABStTm_IMM8_08 "电压稳定时间_IMM8";
CM_ SG_ 2332108953 CRC_M2I_Byrack_IMM8_09 "CRC校验_IMM8";
CM_ SG_ 2332108953 M2I_Byrack_HVS_IMM8_09 "绝缘测量电压_IMM8";
CM_ SG_ 2332108953 M2I_Byrack_Enable_IMM8_09 "绝缘采样使能位_IMM8";
CM_ SG_ 2332108953 M2I_Byrack_ReVeEnable_IMM8_09 "读取软件版本使能位_IMM8";
CM_ SG_ 2332108953 Reserved_09 "预留预留";
CM_ SG_ 2332108953 M2I_Byrack_IsPostTm_IMM8_09 "绝缘采样时间_IMM8";
CM_ SG_ 2332108953 M2I_Byrack_SysABStTm_IMM8_09 "电压稳定时间_IMM8";
CM_ SG_ 2332108954 CRC_M2I_Byrack_IMM8_10 "CRC校验_IMM8";
CM_ SG_ 2332108954 M2I_Byrack_HVS_IMM8_10 "绝缘测量电压_IMM8";
CM_ SG_ 2332108954 M2I_Byrack_Enable_IMM8_10 "绝缘采样使能位_IMM8";
CM_ SG_ 2332108954 M2I_Byrack_ReVeEnable_IMM8_10 "读取软件版本使能位_IMM8";
CM_ SG_ 2332108954 Reserved_10 "预留预留";
CM_ SG_ 2332108954 M2I_Byrack_IsPostTm_IMM8_10 "绝缘采样时间_IMM8";
CM_ SG_ 2332108954 M2I_Byrack_SysABStTm_IMM8_10 "电压稳定时间_IMM8";
CM_ SG_ 2332108955 CRC_M2I_Byrack_IMM8_11 "CRC校验_IMM8";
CM_ SG_ 2332108955 M2I_Byrack_HVS_IMM8_11 "绝缘测量电压_IMM8";
CM_ SG_ 2332108955 M2I_Byrack_Enable_IMM8_11 "绝缘采样使能位_IMM8";
CM_ SG_ 2332108955 M2I_Byrack_ReVeEnable_IMM8_11 "读取软件版本使能位_IMM8";
CM_ SG_ 2332108955 Reserved_11 "预留预留";
CM_ SG_ 2332108955 M2I_Byrack_IsPostTm_IMM8_11 "绝缘采样时间_IMM8";
CM_ SG_ 2332108955 M2I_Byrack_SysABStTm_IMM8_11 "电压稳定时间_IMM8";
CM_ SG_ 2332108956 CRC_M2I_Byrack_IMM8_12 "CRC校验_IMM8";
CM_ SG_ 2332108956 M2I_Byrack_HVS_IMM8_12 "绝缘测量电压_IMM8";
CM_ SG_ 2332108956 M2I_Byrack_Enable_IMM8_12 "绝缘采样使能位_IMM8";
CM_ SG_ 2332108956 M2I_Byrack_ReVeEnable_IMM8_12 "读取软件版本使能位_IMM8";
CM_ SG_ 2332108956 Reserved_12 "预留预留";
CM_ SG_ 2332108956 M2I_Byrack_IsPostTm_IMM8_12 "绝缘采样时间_IMM8";
CM_ SG_ 2332108956 M2I_Byrack_SysABStTm_IMM8_12 "电压稳定时间_IMM8";
CM_ SG_ 2332108957 CRC_M2I_Byrack_IMM8_13 "CRC校验_IMM8";
CM_ SG_ 2332108957 M2I_Byrack_HVS_IMM8_13 "绝缘测量电压_IMM8";
CM_ SG_ 2332108957 M2I_Byrack_Enable_IMM8_13 "绝缘采样使能位_IMM8";
CM_ SG_ 2332108957 M2I_Byrack_ReVeEnable_IMM8_13 "读取软件版本使能位_IMM8";
CM_ SG_ 2332108957 Reserved_13 "预留预留";
CM_ SG_ 2332108957 M2I_Byrack_IsPostTm_IMM8_13 "绝缘采样时间_IMM8";
CM_ SG_ 2332108957 M2I_Byrack_SysABStTm_IMM8_13 "电压稳定时间_IMM8";
CM_ SG_ 2332108958 CRC_M2I_Byrack_IMM8_14 "CRC校验_IMM8";
CM_ SG_ 2332108958 M2I_Byrack_HVS_IMM8_14 "绝缘测量电压_IMM8";
CM_ SG_ 2332108958 M2I_Byrack_Enable_IMM8_14 "绝缘采样使能位_IMM8";
CM_ SG_ 2332108958 M2I_Byrack_ReVeEnable_IMM8_14 "读取软件版本使能位_IMM8";
CM_ SG_ 2332108958 Reserved_14 "预留预留";
CM_ SG_ 2332108958 M2I_Byrack_IsPostTm_IMM8_14 "绝缘采样时间_IMM8";
CM_ SG_ 2332108958 M2I_Byrack_SysABStTm_IMM8_14 "电压稳定时间_IMM8";
CM_ SG_ 2332108959 CRC_M2I_Byrack_IMM8_15 "CRC校验_IMM8";
CM_ SG_ 2332108959 M2I_Byrack_HVS_IMM8_15 "绝缘测量电压_IMM8";
CM_ SG_ 2332108959 M2I_Byrack_Enable_IMM8_15 "绝缘采样使能位_IMM8";
CM_ SG_ 2332108959 M2I_Byrack_ReVeEnable_IMM8_15 "读取软件版本使能位_IMM8";
CM_ SG_ 2332108959 Reserved_15 "预留预留";
CM_ SG_ 2332108959 M2I_Byrack_IsPostTm_IMM8_15 "绝缘采样时间_IMM8";
CM_ SG_ 2332108959 M2I_Byrack_SysABStTm_IMM8_15 "电压稳定时间_IMM8";
CM_ SG_ 2332108960 CRC_M2I_Byrack_IMM8_16 "CRC校验_IMM8";
CM_ SG_ 2332108960 M2I_Byrack_HVS_IMM8_16 "绝缘测量电压_IMM8";
CM_ SG_ 2332108960 M2I_Byrack_Enable_IMM8_16 "绝缘采样使能位_IMM8";
CM_ SG_ 2332108960 M2I_Byrack_ReVeEnable_IMM8_16 "读取软件版本使能位_IMM8";
CM_ SG_ 2332108960 Reserved_16 "预留预留";
CM_ SG_ 2332108960 M2I_Byrack_IsPostTm_IMM8_16 "绝缘采样时间_IMM8";
CM_ SG_ 2332108960 M2I_Byrack_SysABStTm_IMM8_16 "电压稳定时间_IMM8";
CM_ SG_ 2332108961 CRC_M2I_Byrack_IMM8_17 "CRC校验_IMM8";
CM_ SG_ 2332108961 M2I_Byrack_HVS_IMM8_17 "绝缘测量电压_IMM8";
CM_ SG_ 2332108961 M2I_Byrack_Enable_IMM8_17 "绝缘采样使能位_IMM8";
CM_ SG_ 2332108961 M2I_Byrack_ReVeEnable_IMM8_17 "读取软件版本使能位_IMM8";
CM_ SG_ 2332108961 Reserved_17 "预留预留";
CM_ SG_ 2332108961 M2I_Byrack_IsPostTm_IMM8_17 "绝缘采样时间_IMM8";
CM_ SG_ 2332108961 M2I_Byrack_SysABStTm_IMM8_17 "电压稳定时间_IMM8";
CM_ SG_ 2332108962 CRC_M2I_Byrack_IMM8_18 "CRC校验_IMM8";
CM_ SG_ 2332108962 M2I_Byrack_HVS_IMM8_18 "绝缘测量电压_IMM8";
CM_ SG_ 2332108962 M2I_Byrack_Enable_IMM8_18 "绝缘采样使能位_IMM8";
CM_ SG_ 2332108962 M2I_Byrack_ReVeEnable_IMM8_18 "读取软件版本使能位_IMM8";
CM_ SG_ 2332108962 Reserved_18 "预留预留";
CM_ SG_ 2332108962 M2I_Byrack_IsPostTm_IMM8_18 "绝缘采样时间_IMM8";
CM_ SG_ 2332108962 M2I_Byrack_SysABStTm_IMM8_18 "电压稳定时间_IMM8";
CM_ SG_ 2332108963 CRC_M2I_Byrack_IMM8_19 "CRC校验_IMM8";
CM_ SG_ 2332108963 M2I_Byrack_HVS_IMM8_19 "绝缘测量电压_IMM8";
CM_ SG_ 2332108963 M2I_Byrack_Enable_IMM8_19 "绝缘采样使能位_IMM8";
CM_ SG_ 2332108963 M2I_Byrack_ReVeEnable_IMM8_19 "读取软件版本使能位_IMM8";
CM_ SG_ 2332108963 Reserved_19 "预留预留";
CM_ SG_ 2332108963 M2I_Byrack_IsPostTm_IMM8_19 "绝缘采样时间_IMM8";
CM_ SG_ 2332108963 M2I_Byrack_SysABStTm_IMM8_19 "电压稳定时间_IMM8";
CM_ SG_ 2332108964 CRC_M2I_Byrack_IMM8_20 "CRC校验_IMM8";
CM_ SG_ 2332108964 M2I_Byrack_HVS_IMM8_20 "绝缘测量电压_IMM8";
CM_ SG_ 2332108964 M2I_Byrack_Enable_IMM8_20 "绝缘采样使能位_IMM8";
CM_ SG_ 2332108964 M2I_Byrack_ReVeEnable_IMM8_20 "读取软件版本使能位_IMM8";
CM_ SG_ 2332108964 Reserved_20 "预留预留";
CM_ SG_ 2332108964 M2I_Byrack_IsPostTm_IMM8_20 "绝缘采样时间_IMM8";
CM_ SG_ 2332108964 M2I_Byrack_SysABStTm_IMM8_20 "电压稳定时间_IMM8";
CM_ SG_ 2332108965 CRC_M2I_Byrack_IMM8_21 "CRC校验_IMM8";
CM_ SG_ 2332108965 M2I_Byrack_HVS_IMM8_21 "绝缘测量电压_IMM8";
CM_ SG_ 2332108965 M2I_Byrack_Enable_IMM8_21 "绝缘采样使能位_IMM8";
CM_ SG_ 2332108965 M2I_Byrack_ReVeEnable_IMM8_21 "读取软件版本使能位_IMM8";
CM_ SG_ 2332108965 Reserved_21 "预留预留";
CM_ SG_ 2332108965 M2I_Byrack_IsPostTm_IMM8_21 "绝缘采样时间_IMM8";
CM_ SG_ 2332108965 M2I_Byrack_SysABStTm_IMM8_21 "电压稳定时间_IMM8";
CM_ SG_ 2332108966 CRC_M2I_Byrack_IMM8_22 "CRC校验_IMM8";
CM_ SG_ 2332108966 M2I_Byrack_HVS_IMM8_22 "绝缘测量电压_IMM8";
CM_ SG_ 2332108966 M2I_Byrack_Enable_IMM8_22 "绝缘采样使能位_IMM8";
CM_ SG_ 2332108966 M2I_Byrack_ReVeEnable_IMM8_22 "读取软件版本使能位_IMM8";
CM_ SG_ 2332108966 Reserved_22 "预留预留";
CM_ SG_ 2332108966 M2I_Byrack_IsPostTm_IMM8_22 "绝缘采样时间_IMM8";
CM_ SG_ 2332108966 M2I_Byrack_SysABStTm_IMM8_22 "电压稳定时间_IMM8";
CM_ SG_ 2332108967 CRC_M2I_Byrack_IMM8_23 "CRC校验_IMM8";
CM_ SG_ 2332108967 M2I_Byrack_HVS_IMM8_23 "绝缘测量电压_IMM8";
CM_ SG_ 2332108967 M2I_Byrack_Enable_IMM8_23 "绝缘采样使能位_IMM8";
CM_ SG_ 2332108967 M2I_Byrack_ReVeEnable_IMM8_23 "读取软件版本使能位_IMM8";
CM_ SG_ 2332108967 Reserved_23 "预留预留";
CM_ SG_ 2332108967 M2I_Byrack_IsPostTm_IMM8_23 "绝缘采样时间_IMM8";
CM_ SG_ 2332108967 M2I_Byrack_SysABStTm_IMM8_23 "电压稳定时间_IMM8";
CM_ SG_ 2332108968 CRC_M2I_Byrack_IMM8_24 "CRC校验_IMM8";
CM_ SG_ 2332108968 M2I_Byrack_HVS_IMM8_24 "绝缘测量电压_IMM8";
CM_ SG_ 2332108968 M2I_Byrack_Enable_IMM8_24 "绝缘采样使能位_IMM8";
CM_ SG_ 2332108968 M2I_Byrack_ReVeEnable_IMM8_24 "读取软件版本使能位_IMM8";
CM_ SG_ 2332108968 Reserved_24 "预留预留";
CM_ SG_ 2332108968 M2I_Byrack_IsPostTm_IMM8_24 "绝缘采样时间_IMM8";
CM_ SG_ 2332108968 M2I_Byrack_SysABStTm_IMM8_24 "电压稳定时间_IMM8";
CM_ SG_ 2332108969 CRC_M2I_Byrack_IMM8_25 "CRC校验_IMM8";
CM_ SG_ 2332108969 M2I_Byrack_HVS_IMM8_25 "绝缘测量电压_IMM8";
CM_ SG_ 2332108969 M2I_Byrack_Enable_IMM8_25 "绝缘采样使能位_IMM8";
CM_ SG_ 2332108969 M2I_Byrack_ReVeEnable_IMM8_25 "读取软件版本使能位_IMM8";
CM_ SG_ 2332108969 Reserved_25 "预留预留";
CM_ SG_ 2332108969 M2I_Byrack_IsPostTm_IMM8_25 "绝缘采样时间_IMM8";
CM_ SG_ 2332108969 M2I_Byrack_SysABStTm_IMM8_25 "电压稳定时间_IMM8";
CM_ SG_ 2332108970 CRC_M2I_Byrack_IMM8_26 "CRC校验_IMM8";
CM_ SG_ 2332108970 M2I_Byrack_HVS_IMM8_26 "绝缘测量电压_IMM8";
CM_ SG_ 2332108970 M2I_Byrack_Enable_IMM8_26 "绝缘采样使能位_IMM8";
CM_ SG_ 2332108970 M2I_Byrack_ReVeEnable_IMM8_26 "读取软件版本使能位_IMM8";
CM_ SG_ 2332108970 Reserved_26 "预留预留";
CM_ SG_ 2332108970 M2I_Byrack_IsPostTm_IMM8_26 "绝缘采样时间_IMM8";
CM_ SG_ 2332108970 M2I_Byrack_SysABStTm_IMM8_26 "电压稳定时间_IMM8";
CM_ SG_ 2332108971 CRC_M2I_Byrack_IMM8_27 "CRC校验_IMM8";
CM_ SG_ 2332108971 M2I_Byrack_HVS_IMM8_27 "绝缘测量电压_IMM8";
CM_ SG_ 2332108971 M2I_Byrack_Enable_IMM8_27 "绝缘采样使能位_IMM8";
CM_ SG_ 2332108971 M2I_Byrack_ReVeEnable_IMM8_27 "读取软件版本使能位_IMM8";
CM_ SG_ 2332108971 Reserved_27 "预留预留";
CM_ SG_ 2332108971 M2I_Byrack_IsPostTm_IMM8_27 "绝缘采样时间_IMM8";
CM_ SG_ 2332108971 M2I_Byrack_SysABStTm_IMM8_27 "电压稳定时间_IMM8";
CM_ SG_ 2332108972 CRC_M2I_Byrack_IMM8_28 "CRC校验_IMM8";
CM_ SG_ 2332108972 M2I_Byrack_HVS_IMM8_28 "绝缘测量电压_IMM8";
CM_ SG_ 2332108972 M2I_Byrack_Enable_IMM8_28 "绝缘采样使能位_IMM8";
CM_ SG_ 2332108972 M2I_Byrack_ReVeEnable_IMM8_28 "读取软件版本使能位_IMM8";
CM_ SG_ 2332108972 Reserved_28 "预留预留";
CM_ SG_ 2332108972 M2I_Byrack_IsPostTm_IMM8_28 "绝缘采样时间_IMM8";
CM_ SG_ 2332108972 M2I_Byrack_SysABStTm_IMM8_28 "电压稳定时间_IMM8";
CM_ SG_ 2332108973 CRC_M2I_Byrack_IMM8_29 "CRC校验_IMM8";
CM_ SG_ 2332108973 M2I_Byrack_HVS_IMM8_29 "绝缘测量电压_IMM8";
CM_ SG_ 2332108973 M2I_Byrack_Enable_IMM8_29 "绝缘采样使能位_IMM8";
CM_ SG_ 2332108973 M2I_Byrack_ReVeEnable_IMM8_29 "读取软件版本使能位_IMM8";
CM_ SG_ 2332108973 Reserved_29 "预留预留";
CM_ SG_ 2332108973 M2I_Byrack_IsPostTm_IMM8_29 "绝缘采样时间_IMM8";
CM_ SG_ 2332108973 M2I_Byrack_SysABStTm_IMM8_29 "电压稳定时间_IMM8";
CM_ SG_ 2332108974 CRC_M2I_Byrack_IMM8_30 "CRC校验_IMM8";
CM_ SG_ 2332108974 M2I_Byrack_HVS_IMM8_30 "绝缘测量电压_IMM8";
CM_ SG_ 2332108974 M2I_Byrack_Enable_IMM8_30 "绝缘采样使能位_IMM8";
CM_ SG_ 2332108974 M2I_Byrack_ReVeEnable_IMM8_30 "读取软件版本使能位_IMM8";
CM_ SG_ 2332108974 Reserved_30 "预留预留";
CM_ SG_ 2332108974 M2I_Byrack_IsPostTm_IMM8_30 "绝缘采样时间_IMM8";
CM_ SG_ 2332108974 M2I_Byrack_SysABStTm_IMM8_30 "电压稳定时间_IMM8";
CM_ SG_ 2332108975 CRC_M2I_Byrack_IMM8_31 "CRC校验_IMM8";
CM_ SG_ 2332108975 M2I_Byrack_HVS_IMM8_31 "绝缘测量电压_IMM8";
CM_ SG_ 2332108975 M2I_Byrack_Enable_IMM8_31 "绝缘采样使能位_IMM8";
CM_ SG_ 2332108975 M2I_Byrack_ReVeEnable_IMM8_31 "读取软件版本使能位_IMM8";
CM_ SG_ 2332108975 Reserved_31 "预留预留";
CM_ SG_ 2332108975 M2I_Byrack_IsPostTm_IMM8_31 "绝缘采样时间_IMM8";
CM_ SG_ 2332108975 M2I_Byrack_SysABStTm_IMM8_31 "电压稳定时间_IMM8";
CM_ SG_ 2332109201 CRC_M2I_Byrack_IMM9_01 "CRC校验_IMM9";
CM_ SG_ 2332109201 M2I_Byrack_HVS_IMM9_01 "绝缘测量电压_IMM9";
CM_ SG_ 2332109201 M2I_Byrack_Enable_IMM9_01 "绝缘采样使能位_IMM9";
CM_ SG_ 2332109201 M2I_Byrack_ReVeEnable_IMM9_01 "读取软件版本使能位_IMM9";
CM_ SG_ 2332109201 Reserved_01 "预留预留";
CM_ SG_ 2332109201 M2I_Byrack_IsPostTm_IMM9_01 "绝缘采样时间_IMM9";
CM_ SG_ 2332109201 M2I_Byrack_SysABStTm_IMM9_01 "电压稳定时间_IMM9";
CM_ SG_ 2332109202 CRC_M2I_Byrack_IMM9_02 "CRC校验_IMM9";
CM_ SG_ 2332109202 M2I_Byrack_HVS_IMM9_02 "绝缘测量电压_IMM9";
CM_ SG_ 2332109202 M2I_Byrack_Enable_IMM9_02 "绝缘采样使能位_IMM9";
CM_ SG_ 2332109202 M2I_Byrack_ReVeEnable_IMM9_02 "读取软件版本使能位_IMM9";
CM_ SG_ 2332109202 Reserved_02 "预留预留";
CM_ SG_ 2332109202 M2I_Byrack_IsPostTm_IMM9_02 "绝缘采样时间_IMM9";
CM_ SG_ 2332109202 M2I_Byrack_SysABStTm_IMM9_02 "电压稳定时间_IMM9";
CM_ SG_ 2332109203 CRC_M2I_Byrack_IMM9_03 "CRC校验_IMM9";
CM_ SG_ 2332109203 M2I_Byrack_HVS_IMM9_03 "绝缘测量电压_IMM9";
CM_ SG_ 2332109203 M2I_Byrack_Enable_IMM9_03 "绝缘采样使能位_IMM9";
CM_ SG_ 2332109203 M2I_Byrack_ReVeEnable_IMM9_03 "读取软件版本使能位_IMM9";
CM_ SG_ 2332109203 Reserved_03 "预留预留";
CM_ SG_ 2332109203 M2I_Byrack_IsPostTm_IMM9_03 "绝缘采样时间_IMM9";
CM_ SG_ 2332109203 M2I_Byrack_SysABStTm_IMM9_03 "电压稳定时间_IMM9";
CM_ SG_ 2332109204 CRC_M2I_Byrack_IMM9_04 "CRC校验_IMM9";
CM_ SG_ 2332109204 M2I_Byrack_HVS_IMM9_04 "绝缘测量电压_IMM9";
CM_ SG_ 2332109204 M2I_Byrack_Enable_IMM9_04 "绝缘采样使能位_IMM9";
CM_ SG_ 2332109204 M2I_Byrack_ReVeEnable_IMM9_04 "读取软件版本使能位_IMM9";
CM_ SG_ 2332109204 Reserved_04 "预留预留";
CM_ SG_ 2332109204 M2I_Byrack_IsPostTm_IMM9_04 "绝缘采样时间_IMM9";
CM_ SG_ 2332109204 M2I_Byrack_SysABStTm_IMM9_04 "电压稳定时间_IMM9";
CM_ SG_ 2332109205 CRC_M2I_Byrack_IMM9_05 "CRC校验_IMM9";
CM_ SG_ 2332109205 M2I_Byrack_HVS_IMM9_05 "绝缘测量电压_IMM9";
CM_ SG_ 2332109205 M2I_Byrack_Enable_IMM9_05 "绝缘采样使能位_IMM9";
CM_ SG_ 2332109205 M2I_Byrack_ReVeEnable_IMM9_05 "读取软件版本使能位_IMM9";
CM_ SG_ 2332109205 Reserved_05 "预留预留";
CM_ SG_ 2332109205 M2I_Byrack_IsPostTm_IMM9_05 "绝缘采样时间_IMM9";
CM_ SG_ 2332109205 M2I_Byrack_SysABStTm_IMM9_05 "电压稳定时间_IMM9";
CM_ SG_ 2332109206 CRC_M2I_Byrack_IMM9_06 "CRC校验_IMM9";
CM_ SG_ 2332109206 M2I_Byrack_HVS_IMM9_06 "绝缘测量电压_IMM9";
CM_ SG_ 2332109206 M2I_Byrack_Enable_IMM9_06 "绝缘采样使能位_IMM9";
CM_ SG_ 2332109206 M2I_Byrack_ReVeEnable_IMM9_06 "读取软件版本使能位_IMM9";
CM_ SG_ 2332109206 Reserved_06 "预留预留";
CM_ SG_ 2332109206 M2I_Byrack_IsPostTm_IMM9_06 "绝缘采样时间_IMM9";
CM_ SG_ 2332109206 M2I_Byrack_SysABStTm_IMM9_06 "电压稳定时间_IMM9";
CM_ SG_ 2332109207 CRC_M2I_Byrack_IMM9_07 "CRC校验_IMM9";
CM_ SG_ 2332109207 M2I_Byrack_HVS_IMM9_07 "绝缘测量电压_IMM9";
CM_ SG_ 2332109207 M2I_Byrack_Enable_IMM9_07 "绝缘采样使能位_IMM9";
CM_ SG_ 2332109207 M2I_Byrack_ReVeEnable_IMM9_07 "读取软件版本使能位_IMM9";
CM_ SG_ 2332109207 Reserved_07 "预留预留";
CM_ SG_ 2332109207 M2I_Byrack_IsPostTm_IMM9_07 "绝缘采样时间_IMM9";
CM_ SG_ 2332109207 M2I_Byrack_SysABStTm_IMM9_07 "电压稳定时间_IMM9";
CM_ SG_ 2332109208 CRC_M2I_Byrack_IMM9_08 "CRC校验_IMM9";
CM_ SG_ 2332109208 M2I_Byrack_HVS_IMM9_08 "绝缘测量电压_IMM9";
CM_ SG_ 2332109208 M2I_Byrack_Enable_IMM9_08 "绝缘采样使能位_IMM9";
CM_ SG_ 2332109208 M2I_Byrack_ReVeEnable_IMM9_08 "读取软件版本使能位_IMM9";
CM_ SG_ 2332109208 Reserved_08 "预留预留";
CM_ SG_ 2332109208 M2I_Byrack_IsPostTm_IMM9_08 "绝缘采样时间_IMM9";
CM_ SG_ 2332109208 M2I_Byrack_SysABStTm_IMM9_08 "电压稳定时间_IMM9";
CM_ SG_ 2332109209 CRC_M2I_Byrack_IMM9_09 "CRC校验_IMM9";
CM_ SG_ 2332109209 M2I_Byrack_HVS_IMM9_09 "绝缘测量电压_IMM9";
CM_ SG_ 2332109209 M2I_Byrack_Enable_IMM9_09 "绝缘采样使能位_IMM9";
CM_ SG_ 2332109209 M2I_Byrack_ReVeEnable_IMM9_09 "读取软件版本使能位_IMM9";
CM_ SG_ 2332109209 Reserved_09 "预留预留";
CM_ SG_ 2332109209 M2I_Byrack_IsPostTm_IMM9_09 "绝缘采样时间_IMM9";
CM_ SG_ 2332109209 M2I_Byrack_SysABStTm_IMM9_09 "电压稳定时间_IMM9";
CM_ SG_ 2332109210 CRC_M2I_Byrack_IMM9_10 "CRC校验_IMM9";
CM_ SG_ 2332109210 M2I_Byrack_HVS_IMM9_10 "绝缘测量电压_IMM9";
CM_ SG_ 2332109210 M2I_Byrack_Enable_IMM9_10 "绝缘采样使能位_IMM9";
CM_ SG_ 2332109210 M2I_Byrack_ReVeEnable_IMM9_10 "读取软件版本使能位_IMM9";
CM_ SG_ 2332109210 Reserved_10 "预留预留";
CM_ SG_ 2332109210 M2I_Byrack_IsPostTm_IMM9_10 "绝缘采样时间_IMM9";
CM_ SG_ 2332109210 M2I_Byrack_SysABStTm_IMM9_10 "电压稳定时间_IMM9";
CM_ SG_ 2332109211 CRC_M2I_Byrack_IMM9_11 "CRC校验_IMM9";
CM_ SG_ 2332109211 M2I_Byrack_HVS_IMM9_11 "绝缘测量电压_IMM9";
CM_ SG_ 2332109211 M2I_Byrack_Enable_IMM9_11 "绝缘采样使能位_IMM9";
CM_ SG_ 2332109211 M2I_Byrack_ReVeEnable_IMM9_11 "读取软件版本使能位_IMM9";
CM_ SG_ 2332109211 Reserved_11 "预留预留";
CM_ SG_ 2332109211 M2I_Byrack_IsPostTm_IMM9_11 "绝缘采样时间_IMM9";
CM_ SG_ 2332109211 M2I_Byrack_SysABStTm_IMM9_11 "电压稳定时间_IMM9";
CM_ SG_ 2332109212 CRC_M2I_Byrack_IMM9_12 "CRC校验_IMM9";
CM_ SG_ 2332109212 M2I_Byrack_HVS_IMM9_12 "绝缘测量电压_IMM9";
CM_ SG_ 2332109212 M2I_Byrack_Enable_IMM9_12 "绝缘采样使能位_IMM9";
CM_ SG_ 2332109212 M2I_Byrack_ReVeEnable_IMM9_12 "读取软件版本使能位_IMM9";
CM_ SG_ 2332109212 Reserved_12 "预留预留";
CM_ SG_ 2332109212 M2I_Byrack_IsPostTm_IMM9_12 "绝缘采样时间_IMM9";
CM_ SG_ 2332109212 M2I_Byrack_SysABStTm_IMM9_12 "电压稳定时间_IMM9";
CM_ SG_ 2332109213 CRC_M2I_Byrack_IMM9_13 "CRC校验_IMM9";
CM_ SG_ 2332109213 M2I_Byrack_HVS_IMM9_13 "绝缘测量电压_IMM9";
CM_ SG_ 2332109213 M2I_Byrack_Enable_IMM9_13 "绝缘采样使能位_IMM9";
CM_ SG_ 2332109213 M2I_Byrack_ReVeEnable_IMM9_13 "读取软件版本使能位_IMM9";
CM_ SG_ 2332109213 Reserved_13 "预留预留";
CM_ SG_ 2332109213 M2I_Byrack_IsPostTm_IMM9_13 "绝缘采样时间_IMM9";
CM_ SG_ 2332109213 M2I_Byrack_SysABStTm_IMM9_13 "电压稳定时间_IMM9";
CM_ SG_ 2332109214 CRC_M2I_Byrack_IMM9_14 "CRC校验_IMM9";
CM_ SG_ 2332109214 M2I_Byrack_HVS_IMM9_14 "绝缘测量电压_IMM9";
CM_ SG_ 2332109214 M2I_Byrack_Enable_IMM9_14 "绝缘采样使能位_IMM9";
CM_ SG_ 2332109214 M2I_Byrack_ReVeEnable_IMM9_14 "读取软件版本使能位_IMM9";
CM_ SG_ 2332109214 Reserved_14 "预留预留";
CM_ SG_ 2332109214 M2I_Byrack_IsPostTm_IMM9_14 "绝缘采样时间_IMM9";
CM_ SG_ 2332109214 M2I_Byrack_SysABStTm_IMM9_14 "电压稳定时间_IMM9";
CM_ SG_ 2332109215 CRC_M2I_Byrack_IMM9_15 "CRC校验_IMM9";
CM_ SG_ 2332109215 M2I_Byrack_HVS_IMM9_15 "绝缘测量电压_IMM9";
CM_ SG_ 2332109215 M2I_Byrack_Enable_IMM9_15 "绝缘采样使能位_IMM9";
CM_ SG_ 2332109215 M2I_Byrack_ReVeEnable_IMM9_15 "读取软件版本使能位_IMM9";
CM_ SG_ 2332109215 Reserved_15 "预留预留";
CM_ SG_ 2332109215 M2I_Byrack_IsPostTm_IMM9_15 "绝缘采样时间_IMM9";
CM_ SG_ 2332109215 M2I_Byrack_SysABStTm_IMM9_15 "电压稳定时间_IMM9";
CM_ SG_ 2332109216 CRC_M2I_Byrack_IMM9_16 "CRC校验_IMM9";
CM_ SG_ 2332109216 M2I_Byrack_HVS_IMM9_16 "绝缘测量电压_IMM9";
CM_ SG_ 2332109216 M2I_Byrack_Enable_IMM9_16 "绝缘采样使能位_IMM9";
CM_ SG_ 2332109216 M2I_Byrack_ReVeEnable_IMM9_16 "读取软件版本使能位_IMM9";
CM_ SG_ 2332109216 Reserved_16 "预留预留";
CM_ SG_ 2332109216 M2I_Byrack_IsPostTm_IMM9_16 "绝缘采样时间_IMM9";
CM_ SG_ 2332109216 M2I_Byrack_SysABStTm_IMM9_16 "电压稳定时间_IMM9";
CM_ SG_ 2332109217 CRC_M2I_Byrack_IMM9_17 "CRC校验_IMM9";
CM_ SG_ 2332109217 M2I_Byrack_HVS_IMM9_17 "绝缘测量电压_IMM9";
CM_ SG_ 2332109217 M2I_Byrack_Enable_IMM9_17 "绝缘采样使能位_IMM9";
CM_ SG_ 2332109217 M2I_Byrack_ReVeEnable_IMM9_17 "读取软件版本使能位_IMM9";
CM_ SG_ 2332109217 Reserved_17 "预留预留";
CM_ SG_ 2332109217 M2I_Byrack_IsPostTm_IMM9_17 "绝缘采样时间_IMM9";
CM_ SG_ 2332109217 M2I_Byrack_SysABStTm_IMM9_17 "电压稳定时间_IMM9";
CM_ SG_ 2332109218 CRC_M2I_Byrack_IMM9_18 "CRC校验_IMM9";
CM_ SG_ 2332109218 M2I_Byrack_HVS_IMM9_18 "绝缘测量电压_IMM9";
CM_ SG_ 2332109218 M2I_Byrack_Enable_IMM9_18 "绝缘采样使能位_IMM9";
CM_ SG_ 2332109218 M2I_Byrack_ReVeEnable_IMM9_18 "读取软件版本使能位_IMM9";
CM_ SG_ 2332109218 Reserved_18 "预留预留";
CM_ SG_ 2332109218 M2I_Byrack_IsPostTm_IMM9_18 "绝缘采样时间_IMM9";
CM_ SG_ 2332109218 M2I_Byrack_SysABStTm_IMM9_18 "电压稳定时间_IMM9";
CM_ SG_ 2332109219 CRC_M2I_Byrack_IMM9_19 "CRC校验_IMM9";
CM_ SG_ 2332109219 M2I_Byrack_HVS_IMM9_19 "绝缘测量电压_IMM9";
CM_ SG_ 2332109219 M2I_Byrack_Enable_IMM9_19 "绝缘采样使能位_IMM9";
CM_ SG_ 2332109219 M2I_Byrack_ReVeEnable_IMM9_19 "读取软件版本使能位_IMM9";
CM_ SG_ 2332109219 Reserved_19 "预留预留";
CM_ SG_ 2332109219 M2I_Byrack_IsPostTm_IMM9_19 "绝缘采样时间_IMM9";
CM_ SG_ 2332109219 M2I_Byrack_SysABStTm_IMM9_19 "电压稳定时间_IMM9";
CM_ SG_ 2332109220 CRC_M2I_Byrack_IMM9_20 "CRC校验_IMM9";
CM_ SG_ 2332109220 M2I_Byrack_HVS_IMM9_20 "绝缘测量电压_IMM9";
CM_ SG_ 2332109220 M2I_Byrack_Enable_IMM9_20 "绝缘采样使能位_IMM9";
CM_ SG_ 2332109220 M2I_Byrack_ReVeEnable_IMM9_20 "读取软件版本使能位_IMM9";
CM_ SG_ 2332109220 Reserved_20 "预留预留";
CM_ SG_ 2332109220 M2I_Byrack_IsPostTm_IMM9_20 "绝缘采样时间_IMM9";
CM_ SG_ 2332109220 M2I_Byrack_SysABStTm_IMM9_20 "电压稳定时间_IMM9";
CM_ SG_ 2332109221 CRC_M2I_Byrack_IMM9_21 "CRC校验_IMM9";
CM_ SG_ 2332109221 M2I_Byrack_HVS_IMM9_21 "绝缘测量电压_IMM9";
CM_ SG_ 2332109221 M2I_Byrack_Enable_IMM9_21 "绝缘采样使能位_IMM9";
CM_ SG_ 2332109221 M2I_Byrack_ReVeEnable_IMM9_21 "读取软件版本使能位_IMM9";
CM_ SG_ 2332109221 Reserved_21 "预留预留";
CM_ SG_ 2332109221 M2I_Byrack_IsPostTm_IMM9_21 "绝缘采样时间_IMM9";
CM_ SG_ 2332109221 M2I_Byrack_SysABStTm_IMM9_21 "电压稳定时间_IMM9";
CM_ SG_ 2332109222 CRC_M2I_Byrack_IMM9_22 "CRC校验_IMM9";
CM_ SG_ 2332109222 M2I_Byrack_HVS_IMM9_22 "绝缘测量电压_IMM9";
CM_ SG_ 2332109222 M2I_Byrack_Enable_IMM9_22 "绝缘采样使能位_IMM9";
CM_ SG_ 2332109222 M2I_Byrack_ReVeEnable_IMM9_22 "读取软件版本使能位_IMM9";
CM_ SG_ 2332109222 Reserved_22 "预留预留";
CM_ SG_ 2332109222 M2I_Byrack_IsPostTm_IMM9_22 "绝缘采样时间_IMM9";
CM_ SG_ 2332109222 M2I_Byrack_SysABStTm_IMM9_22 "电压稳定时间_IMM9";
CM_ SG_ 2332109223 CRC_M2I_Byrack_IMM9_23 "CRC校验_IMM9";
CM_ SG_ 2332109223 M2I_Byrack_HVS_IMM9_23 "绝缘测量电压_IMM9";
CM_ SG_ 2332109223 M2I_Byrack_Enable_IMM9_23 "绝缘采样使能位_IMM9";
CM_ SG_ 2332109223 M2I_Byrack_ReVeEnable_IMM9_23 "读取软件版本使能位_IMM9";
CM_ SG_ 2332109223 Reserved_23 "预留预留";
CM_ SG_ 2332109223 M2I_Byrack_IsPostTm_IMM9_23 "绝缘采样时间_IMM9";
CM_ SG_ 2332109223 M2I_Byrack_SysABStTm_IMM9_23 "电压稳定时间_IMM9";
CM_ SG_ 2332109224 CRC_M2I_Byrack_IMM9_24 "CRC校验_IMM9";
CM_ SG_ 2332109224 M2I_Byrack_HVS_IMM9_24 "绝缘测量电压_IMM9";
CM_ SG_ 2332109224 M2I_Byrack_Enable_IMM9_24 "绝缘采样使能位_IMM9";
CM_ SG_ 2332109224 M2I_Byrack_ReVeEnable_IMM9_24 "读取软件版本使能位_IMM9";
CM_ SG_ 2332109224 Reserved_24 "预留预留";
CM_ SG_ 2332109224 M2I_Byrack_IsPostTm_IMM9_24 "绝缘采样时间_IMM9";
CM_ SG_ 2332109224 M2I_Byrack_SysABStTm_IMM9_24 "电压稳定时间_IMM9";
CM_ SG_ 2332109225 CRC_M2I_Byrack_IMM9_25 "CRC校验_IMM9";
CM_ SG_ 2332109225 M2I_Byrack_HVS_IMM9_25 "绝缘测量电压_IMM9";
CM_ SG_ 2332109225 M2I_Byrack_Enable_IMM9_25 "绝缘采样使能位_IMM9";
CM_ SG_ 2332109225 M2I_Byrack_ReVeEnable_IMM9_25 "读取软件版本使能位_IMM9";
CM_ SG_ 2332109225 Reserved_25 "预留预留";
CM_ SG_ 2332109225 M2I_Byrack_IsPostTm_IMM9_25 "绝缘采样时间_IMM9";
CM_ SG_ 2332109225 M2I_Byrack_SysABStTm_IMM9_25 "电压稳定时间_IMM9";
CM_ SG_ 2332109226 CRC_M2I_Byrack_IMM9_26 "CRC校验_IMM9";
CM_ SG_ 2332109226 M2I_Byrack_HVS_IMM9_26 "绝缘测量电压_IMM9";
CM_ SG_ 2332109226 M2I_Byrack_Enable_IMM9_26 "绝缘采样使能位_IMM9";
CM_ SG_ 2332109226 M2I_Byrack_ReVeEnable_IMM9_26 "读取软件版本使能位_IMM9";
CM_ SG_ 2332109226 Reserved_26 "预留预留";
CM_ SG_ 2332109226 M2I_Byrack_IsPostTm_IMM9_26 "绝缘采样时间_IMM9";
CM_ SG_ 2332109226 M2I_Byrack_SysABStTm_IMM9_26 "电压稳定时间_IMM9";
CM_ SG_ 2332109227 CRC_M2I_Byrack_IMM9_27 "CRC校验_IMM9";
CM_ SG_ 2332109227 M2I_Byrack_HVS_IMM9_27 "绝缘测量电压_IMM9";
CM_ SG_ 2332109227 M2I_Byrack_Enable_IMM9_27 "绝缘采样使能位_IMM9";
CM_ SG_ 2332109227 M2I_Byrack_ReVeEnable_IMM9_27 "读取软件版本使能位_IMM9";
CM_ SG_ 2332109227 Reserved_27 "预留预留";
CM_ SG_ 2332109227 M2I_Byrack_IsPostTm_IMM9_27 "绝缘采样时间_IMM9";
CM_ SG_ 2332109227 M2I_Byrack_SysABStTm_IMM9_27 "电压稳定时间_IMM9";
CM_ SG_ 2332109228 CRC_M2I_Byrack_IMM9_28 "CRC校验_IMM9";
CM_ SG_ 2332109228 M2I_Byrack_HVS_IMM9_28 "绝缘测量电压_IMM9";
CM_ SG_ 2332109228 M2I_Byrack_Enable_IMM9_28 "绝缘采样使能位_IMM9";
CM_ SG_ 2332109228 M2I_Byrack_ReVeEnable_IMM9_28 "读取软件版本使能位_IMM9";
CM_ SG_ 2332109228 Reserved_28 "预留预留";
CM_ SG_ 2332109228 M2I_Byrack_IsPostTm_IMM9_28 "绝缘采样时间_IMM9";
CM_ SG_ 2332109228 M2I_Byrack_SysABStTm_IMM9_28 "电压稳定时间_IMM9";
CM_ SG_ 2332109229 CRC_M2I_Byrack_IMM9_29 "CRC校验_IMM9";
CM_ SG_ 2332109229 M2I_Byrack_HVS_IMM9_29 "绝缘测量电压_IMM9";
CM_ SG_ 2332109229 M2I_Byrack_Enable_IMM9_29 "绝缘采样使能位_IMM9";
CM_ SG_ 2332109229 M2I_Byrack_ReVeEnable_IMM9_29 "读取软件版本使能位_IMM9";
CM_ SG_ 2332109229 Reserved_29 "预留预留";
CM_ SG_ 2332109229 M2I_Byrack_IsPostTm_IMM9_29 "绝缘采样时间_IMM9";
CM_ SG_ 2332109229 M2I_Byrack_SysABStTm_IMM9_29 "电压稳定时间_IMM9";
CM_ SG_ 2332109230 CRC_M2I_Byrack_IMM9_30 "CRC校验_IMM9";
CM_ SG_ 2332109230 M2I_Byrack_HVS_IMM9_30 "绝缘测量电压_IMM9";
CM_ SG_ 2332109230 M2I_Byrack_Enable_IMM9_30 "绝缘采样使能位_IMM9";
CM_ SG_ 2332109230 M2I_Byrack_ReVeEnable_IMM9_30 "读取软件版本使能位_IMM9";
CM_ SG_ 2332109230 Reserved_30 "预留预留";
CM_ SG_ 2332109230 M2I_Byrack_IsPostTm_IMM9_30 "绝缘采样时间_IMM9";
CM_ SG_ 2332109230 M2I_Byrack_SysABStTm_IMM9_30 "电压稳定时间_IMM9";
CM_ SG_ 2332109231 CRC_M2I_Byrack_IMM9_31 "CRC校验_IMM9";
CM_ SG_ 2332109231 M2I_Byrack_HVS_IMM9_31 "绝缘测量电压_IMM9";
CM_ SG_ 2332109231 M2I_Byrack_Enable_IMM9_31 "绝缘采样使能位_IMM9";
CM_ SG_ 2332109231 M2I_Byrack_ReVeEnable_IMM9_31 "读取软件版本使能位_IMM9";
CM_ SG_ 2332109231 Reserved_31 "预留预留";
CM_ SG_ 2332109231 M2I_Byrack_IsPostTm_IMM9_31 "绝缘采样时间_IMM9";
CM_ SG_ 2332109231 M2I_Byrack_SysABStTm_IMM9_31 "电压稳定时间_IMM9";
CM_ SG_ 2332109457 CRC_M2I_Byrack_IMM10_01 "CRC校验_IMM10";
CM_ SG_ 2332109457 M2I_Byrack_HVS_IMM10_01 "绝缘测量电压_IMM10";
CM_ SG_ 2332109457 M2I_Byrack_Enable_IMM10_01 "绝缘采样使能位_IMM10";
CM_ SG_ 2332109457 M2I_Byrack_ReVeEnable_IMM10_01 "读取软件版本使能位_IMM10";
CM_ SG_ 2332109457 Reserved_01 "预留预留";
CM_ SG_ 2332109457 M2I_Byrack_IsPostTm_IMM10_01 "绝缘采样时间_IMM10";
CM_ SG_ 2332109457 M2I_Byrack_SysABStTm_IMM10_01 "电压稳定时间_IMM10";
CM_ SG_ 2332109458 CRC_M2I_Byrack_IMM10_02 "CRC校验_IMM10";
CM_ SG_ 2332109458 M2I_Byrack_HVS_IMM10_02 "绝缘测量电压_IMM10";
CM_ SG_ 2332109458 M2I_Byrack_Enable_IMM10_02 "绝缘采样使能位_IMM10";
CM_ SG_ 2332109458 M2I_Byrack_ReVeEnable_IMM10_02 "读取软件版本使能位_IMM10";
CM_ SG_ 2332109458 Reserved_02 "预留预留";
CM_ SG_ 2332109458 M2I_Byrack_IsPostTm_IMM10_02 "绝缘采样时间_IMM10";
CM_ SG_ 2332109458 M2I_Byrack_SysABStTm_IMM10_02 "电压稳定时间_IMM10";
CM_ SG_ 2332109459 CRC_M2I_Byrack_IMM10_03 "CRC校验_IMM10";
CM_ SG_ 2332109459 M2I_Byrack_HVS_IMM10_03 "绝缘测量电压_IMM10";
CM_ SG_ 2332109459 M2I_Byrack_Enable_IMM10_03 "绝缘采样使能位_IMM10";
CM_ SG_ 2332109459 M2I_Byrack_ReVeEnable_IMM10_03 "读取软件版本使能位_IMM10";
CM_ SG_ 2332109459 Reserved_03 "预留预留";
CM_ SG_ 2332109459 M2I_Byrack_IsPostTm_IMM10_03 "绝缘采样时间_IMM10";
CM_ SG_ 2332109459 M2I_Byrack_SysABStTm_IMM10_03 "电压稳定时间_IMM10";
CM_ SG_ 2332109460 CRC_M2I_Byrack_IMM10_04 "CRC校验_IMM10";
CM_ SG_ 2332109460 M2I_Byrack_HVS_IMM10_04 "绝缘测量电压_IMM10";
CM_ SG_ 2332109460 M2I_Byrack_Enable_IMM10_04 "绝缘采样使能位_IMM10";
CM_ SG_ 2332109460 M2I_Byrack_ReVeEnable_IMM10_04 "读取软件版本使能位_IMM10";
CM_ SG_ 2332109460 Reserved_04 "预留预留";
CM_ SG_ 2332109460 M2I_Byrack_IsPostTm_IMM10_04 "绝缘采样时间_IMM10";
CM_ SG_ 2332109460 M2I_Byrack_SysABStTm_IMM10_04 "电压稳定时间_IMM10";
CM_ SG_ 2332109461 CRC_M2I_Byrack_IMM10_05 "CRC校验_IMM10";
CM_ SG_ 2332109461 M2I_Byrack_HVS_IMM10_05 "绝缘测量电压_IMM10";
CM_ SG_ 2332109461 M2I_Byrack_Enable_IMM10_05 "绝缘采样使能位_IMM10";
CM_ SG_ 2332109461 M2I_Byrack_ReVeEnable_IMM10_05 "读取软件版本使能位_IMM10";
CM_ SG_ 2332109461 Reserved_05 "预留预留";
CM_ SG_ 2332109461 M2I_Byrack_IsPostTm_IMM10_05 "绝缘采样时间_IMM10";
CM_ SG_ 2332109461 M2I_Byrack_SysABStTm_IMM10_05 "电压稳定时间_IMM10";
CM_ SG_ 2332109462 CRC_M2I_Byrack_IMM10_06 "CRC校验_IMM10";
CM_ SG_ 2332109462 M2I_Byrack_HVS_IMM10_06 "绝缘测量电压_IMM10";
CM_ SG_ 2332109462 M2I_Byrack_Enable_IMM10_06 "绝缘采样使能位_IMM10";
CM_ SG_ 2332109462 M2I_Byrack_ReVeEnable_IMM10_06 "读取软件版本使能位_IMM10";
CM_ SG_ 2332109462 Reserved_06 "预留预留";
CM_ SG_ 2332109462 M2I_Byrack_IsPostTm_IMM10_06 "绝缘采样时间_IMM10";
CM_ SG_ 2332109462 M2I_Byrack_SysABStTm_IMM10_06 "电压稳定时间_IMM10";
CM_ SG_ 2332109463 CRC_M2I_Byrack_IMM10_07 "CRC校验_IMM10";
CM_ SG_ 2332109463 M2I_Byrack_HVS_IMM10_07 "绝缘测量电压_IMM10";
CM_ SG_ 2332109463 M2I_Byrack_Enable_IMM10_07 "绝缘采样使能位_IMM10";
CM_ SG_ 2332109463 M2I_Byrack_ReVeEnable_IMM10_07 "读取软件版本使能位_IMM10";
CM_ SG_ 2332109463 Reserved_07 "预留预留";
CM_ SG_ 2332109463 M2I_Byrack_IsPostTm_IMM10_07 "绝缘采样时间_IMM10";
CM_ SG_ 2332109463 M2I_Byrack_SysABStTm_IMM10_07 "电压稳定时间_IMM10";
CM_ SG_ 2332109464 CRC_M2I_Byrack_IMM10_08 "CRC校验_IMM10";
CM_ SG_ 2332109464 M2I_Byrack_HVS_IMM10_08 "绝缘测量电压_IMM10";
CM_ SG_ 2332109464 M2I_Byrack_Enable_IMM10_08 "绝缘采样使能位_IMM10";
CM_ SG_ 2332109464 M2I_Byrack_ReVeEnable_IMM10_08 "读取软件版本使能位_IMM10";
CM_ SG_ 2332109464 Reserved_08 "预留预留";
CM_ SG_ 2332109464 M2I_Byrack_IsPostTm_IMM10_08 "绝缘采样时间_IMM10";
CM_ SG_ 2332109464 M2I_Byrack_SysABStTm_IMM10_08 "电压稳定时间_IMM10";
CM_ SG_ 2332109465 CRC_M2I_Byrack_IMM10_09 "CRC校验_IMM10";
CM_ SG_ 2332109465 M2I_Byrack_HVS_IMM10_09 "绝缘测量电压_IMM10";
CM_ SG_ 2332109465 M2I_Byrack_Enable_IMM10_09 "绝缘采样使能位_IMM10";
CM_ SG_ 2332109465 M2I_Byrack_ReVeEnable_IMM10_09 "读取软件版本使能位_IMM10";
CM_ SG_ 2332109465 Reserved_09 "预留预留";
CM_ SG_ 2332109465 M2I_Byrack_IsPostTm_IMM10_09 "绝缘采样时间_IMM10";
CM_ SG_ 2332109465 M2I_Byrack_SysABStTm_IMM10_09 "电压稳定时间_IMM10";
CM_ SG_ 2332109466 CRC_M2I_Byrack_IMM10_10 "CRC校验_IMM10";
CM_ SG_ 2332109466 M2I_Byrack_HVS_IMM10_10 "绝缘测量电压_IMM10";
CM_ SG_ 2332109466 M2I_Byrack_Enable_IMM10_10 "绝缘采样使能位_IMM10";
CM_ SG_ 2332109466 M2I_Byrack_ReVeEnable_IMM10_10 "读取软件版本使能位_IMM10";
CM_ SG_ 2332109466 Reserved_10 "预留预留";
CM_ SG_ 2332109466 M2I_Byrack_IsPostTm_IMM10_10 "绝缘采样时间_IMM10";
CM_ SG_ 2332109466 M2I_Byrack_SysABStTm_IMM10_10 "电压稳定时间_IMM10";
CM_ SG_ 2332109467 CRC_M2I_Byrack_IMM10_11 "CRC校验_IMM10";
CM_ SG_ 2332109467 M2I_Byrack_HVS_IMM10_11 "绝缘测量电压_IMM10";
CM_ SG_ 2332109467 M2I_Byrack_Enable_IMM10_11 "绝缘采样使能位_IMM10";
CM_ SG_ 2332109467 M2I_Byrack_ReVeEnable_IMM10_11 "读取软件版本使能位_IMM10";
CM_ SG_ 2332109467 Reserved_11 "预留预留";
CM_ SG_ 2332109467 M2I_Byrack_IsPostTm_IMM10_11 "绝缘采样时间_IMM10";
CM_ SG_ 2332109467 M2I_Byrack_SysABStTm_IMM10_11 "电压稳定时间_IMM10";
CM_ SG_ 2332109468 CRC_M2I_Byrack_IMM10_12 "CRC校验_IMM10";
CM_ SG_ 2332109468 M2I_Byrack_HVS_IMM10_12 "绝缘测量电压_IMM10";
CM_ SG_ 2332109468 M2I_Byrack_Enable_IMM10_12 "绝缘采样使能位_IMM10";
CM_ SG_ 2332109468 M2I_Byrack_ReVeEnable_IMM10_12 "读取软件版本使能位_IMM10";
CM_ SG_ 2332109468 Reserved_12 "预留预留";
CM_ SG_ 2332109468 M2I_Byrack_IsPostTm_IMM10_12 "绝缘采样时间_IMM10";
CM_ SG_ 2332109468 M2I_Byrack_SysABStTm_IMM10_12 "电压稳定时间_IMM10";
CM_ SG_ 2332109469 CRC_M2I_Byrack_IMM10_13 "CRC校验_IMM10";
CM_ SG_ 2332109469 M2I_Byrack_HVS_IMM10_13 "绝缘测量电压_IMM10";
CM_ SG_ 2332109469 M2I_Byrack_Enable_IMM10_13 "绝缘采样使能位_IMM10";
CM_ SG_ 2332109469 M2I_Byrack_ReVeEnable_IMM10_13 "读取软件版本使能位_IMM10";
CM_ SG_ 2332109469 Reserved_13 "预留预留";
CM_ SG_ 2332109469 M2I_Byrack_IsPostTm_IMM10_13 "绝缘采样时间_IMM10";
CM_ SG_ 2332109469 M2I_Byrack_SysABStTm_IMM10_13 "电压稳定时间_IMM10";
CM_ SG_ 2332109470 CRC_M2I_Byrack_IMM10_14 "CRC校验_IMM10";
CM_ SG_ 2332109470 M2I_Byrack_HVS_IMM10_14 "绝缘测量电压_IMM10";
CM_ SG_ 2332109470 M2I_Byrack_Enable_IMM10_14 "绝缘采样使能位_IMM10";
CM_ SG_ 2332109470 M2I_Byrack_ReVeEnable_IMM10_14 "读取软件版本使能位_IMM10";
CM_ SG_ 2332109470 Reserved_14 "预留预留";
CM_ SG_ 2332109470 M2I_Byrack_IsPostTm_IMM10_14 "绝缘采样时间_IMM10";
CM_ SG_ 2332109470 M2I_Byrack_SysABStTm_IMM10_14 "电压稳定时间_IMM10";
CM_ SG_ 2332109471 CRC_M2I_Byrack_IMM10_15 "CRC校验_IMM10";
CM_ SG_ 2332109471 M2I_Byrack_HVS_IMM10_15 "绝缘测量电压_IMM10";
CM_ SG_ 2332109471 M2I_Byrack_Enable_IMM10_15 "绝缘采样使能位_IMM10";
CM_ SG_ 2332109471 M2I_Byrack_ReVeEnable_IMM10_15 "读取软件版本使能位_IMM10";
CM_ SG_ 2332109471 Reserved_15 "预留预留";
CM_ SG_ 2332109471 M2I_Byrack_IsPostTm_IMM10_15 "绝缘采样时间_IMM10";
CM_ SG_ 2332109471 M2I_Byrack_SysABStTm_IMM10_15 "电压稳定时间_IMM10";
CM_ SG_ 2332109472 CRC_M2I_Byrack_IMM10_16 "CRC校验_IMM10";
CM_ SG_ 2332109472 M2I_Byrack_HVS_IMM10_16 "绝缘测量电压_IMM10";
CM_ SG_ 2332109472 M2I_Byrack_Enable_IMM10_16 "绝缘采样使能位_IMM10";
CM_ SG_ 2332109472 M2I_Byrack_ReVeEnable_IMM10_16 "读取软件版本使能位_IMM10";
CM_ SG_ 2332109472 Reserved_16 "预留预留";
CM_ SG_ 2332109472 M2I_Byrack_IsPostTm_IMM10_16 "绝缘采样时间_IMM10";
CM_ SG_ 2332109472 M2I_Byrack_SysABStTm_IMM10_16 "电压稳定时间_IMM10";
CM_ SG_ 2332109473 CRC_M2I_Byrack_IMM10_17 "CRC校验_IMM10";
CM_ SG_ 2332109473 M2I_Byrack_HVS_IMM10_17 "绝缘测量电压_IMM10";
CM_ SG_ 2332109473 M2I_Byrack_Enable_IMM10_17 "绝缘采样使能位_IMM10";
CM_ SG_ 2332109473 M2I_Byrack_ReVeEnable_IMM10_17 "读取软件版本使能位_IMM10";
CM_ SG_ 2332109473 Reserved_17 "预留预留";
CM_ SG_ 2332109473 M2I_Byrack_IsPostTm_IMM10_17 "绝缘采样时间_IMM10";
CM_ SG_ 2332109473 M2I_Byrack_SysABStTm_IMM10_17 "电压稳定时间_IMM10";
CM_ SG_ 2332109474 CRC_M2I_Byrack_IMM10_18 "CRC校验_IMM10";
CM_ SG_ 2332109474 M2I_Byrack_HVS_IMM10_18 "绝缘测量电压_IMM10";
CM_ SG_ 2332109474 M2I_Byrack_Enable_IMM10_18 "绝缘采样使能位_IMM10";
CM_ SG_ 2332109474 M2I_Byrack_ReVeEnable_IMM10_18 "读取软件版本使能位_IMM10";
CM_ SG_ 2332109474 Reserved_18 "预留预留";
CM_ SG_ 2332109474 M2I_Byrack_IsPostTm_IMM10_18 "绝缘采样时间_IMM10";
CM_ SG_ 2332109474 M2I_Byrack_SysABStTm_IMM10_18 "电压稳定时间_IMM10";
CM_ SG_ 2332109475 CRC_M2I_Byrack_IMM10_19 "CRC校验_IMM10";
CM_ SG_ 2332109475 M2I_Byrack_HVS_IMM10_19 "绝缘测量电压_IMM10";
CM_ SG_ 2332109475 M2I_Byrack_Enable_IMM10_19 "绝缘采样使能位_IMM10";
CM_ SG_ 2332109475 M2I_Byrack_ReVeEnable_IMM10_19 "读取软件版本使能位_IMM10";
CM_ SG_ 2332109475 Reserved_19 "预留预留";
CM_ SG_ 2332109475 M2I_Byrack_IsPostTm_IMM10_19 "绝缘采样时间_IMM10";
CM_ SG_ 2332109475 M2I_Byrack_SysABStTm_IMM10_19 "电压稳定时间_IMM10";
CM_ SG_ 2332109476 CRC_M2I_Byrack_IMM10_20 "CRC校验_IMM10";
CM_ SG_ 2332109476 M2I_Byrack_HVS_IMM10_20 "绝缘测量电压_IMM10";
CM_ SG_ 2332109476 M2I_Byrack_Enable_IMM10_20 "绝缘采样使能位_IMM10";
CM_ SG_ 2332109476 M2I_Byrack_ReVeEnable_IMM10_20 "读取软件版本使能位_IMM10";
CM_ SG_ 2332109476 Reserved_20 "预留预留";
CM_ SG_ 2332109476 M2I_Byrack_IsPostTm_IMM10_20 "绝缘采样时间_IMM10";
CM_ SG_ 2332109476 M2I_Byrack_SysABStTm_IMM10_20 "电压稳定时间_IMM10";
CM_ SG_ 2332109477 CRC_M2I_Byrack_IMM10_21 "CRC校验_IMM10";
CM_ SG_ 2332109477 M2I_Byrack_HVS_IMM10_21 "绝缘测量电压_IMM10";
CM_ SG_ 2332109477 M2I_Byrack_Enable_IMM10_21 "绝缘采样使能位_IMM10";
CM_ SG_ 2332109477 M2I_Byrack_ReVeEnable_IMM10_21 "读取软件版本使能位_IMM10";
CM_ SG_ 2332109477 Reserved_21 "预留预留";
CM_ SG_ 2332109477 M2I_Byrack_IsPostTm_IMM10_21 "绝缘采样时间_IMM10";
CM_ SG_ 2332109477 M2I_Byrack_SysABStTm_IMM10_21 "电压稳定时间_IMM10";
CM_ SG_ 2332109478 CRC_M2I_Byrack_IMM10_22 "CRC校验_IMM10";
CM_ SG_ 2332109478 M2I_Byrack_HVS_IMM10_22 "绝缘测量电压_IMM10";
CM_ SG_ 2332109478 M2I_Byrack_Enable_IMM10_22 "绝缘采样使能位_IMM10";
CM_ SG_ 2332109478 M2I_Byrack_ReVeEnable_IMM10_22 "读取软件版本使能位_IMM10";
CM_ SG_ 2332109478 Reserved_22 "预留预留";
CM_ SG_ 2332109478 M2I_Byrack_IsPostTm_IMM10_22 "绝缘采样时间_IMM10";
CM_ SG_ 2332109478 M2I_Byrack_SysABStTm_IMM10_22 "电压稳定时间_IMM10";
CM_ SG_ 2332109479 CRC_M2I_Byrack_IMM10_23 "CRC校验_IMM10";
CM_ SG_ 2332109479 M2I_Byrack_HVS_IMM10_23 "绝缘测量电压_IMM10";
CM_ SG_ 2332109479 M2I_Byrack_Enable_IMM10_23 "绝缘采样使能位_IMM10";
CM_ SG_ 2332109479 M2I_Byrack_ReVeEnable_IMM10_23 "读取软件版本使能位_IMM10";
CM_ SG_ 2332109479 Reserved_23 "预留预留";
CM_ SG_ 2332109479 M2I_Byrack_IsPostTm_IMM10_23 "绝缘采样时间_IMM10";
CM_ SG_ 2332109479 M2I_Byrack_SysABStTm_IMM10_23 "电压稳定时间_IMM10";
CM_ SG_ 2332109480 CRC_M2I_Byrack_IMM10_24 "CRC校验_IMM10";
CM_ SG_ 2332109480 M2I_Byrack_HVS_IMM10_24 "绝缘测量电压_IMM10";
CM_ SG_ 2332109480 M2I_Byrack_Enable_IMM10_24 "绝缘采样使能位_IMM10";
CM_ SG_ 2332109480 M2I_Byrack_ReVeEnable_IMM10_24 "读取软件版本使能位_IMM10";
CM_ SG_ 2332109480 Reserved_24 "预留预留";
CM_ SG_ 2332109480 M2I_Byrack_IsPostTm_IMM10_24 "绝缘采样时间_IMM10";
CM_ SG_ 2332109480 M2I_Byrack_SysABStTm_IMM10_24 "电压稳定时间_IMM10";
CM_ SG_ 2332109481 CRC_M2I_Byrack_IMM10_25 "CRC校验_IMM10";
CM_ SG_ 2332109481 M2I_Byrack_HVS_IMM10_25 "绝缘测量电压_IMM10";
CM_ SG_ 2332109481 M2I_Byrack_Enable_IMM10_25 "绝缘采样使能位_IMM10";
CM_ SG_ 2332109481 M2I_Byrack_ReVeEnable_IMM10_25 "读取软件版本使能位_IMM10";
CM_ SG_ 2332109481 Reserved_25 "预留预留";
CM_ SG_ 2332109481 M2I_Byrack_IsPostTm_IMM10_25 "绝缘采样时间_IMM10";
CM_ SG_ 2332109481 M2I_Byrack_SysABStTm_IMM10_25 "电压稳定时间_IMM10";
CM_ SG_ 2332109482 CRC_M2I_Byrack_IMM10_26 "CRC校验_IMM10";
CM_ SG_ 2332109482 M2I_Byrack_HVS_IMM10_26 "绝缘测量电压_IMM10";
CM_ SG_ 2332109482 M2I_Byrack_Enable_IMM10_26 "绝缘采样使能位_IMM10";
CM_ SG_ 2332109482 M2I_Byrack_ReVeEnable_IMM10_26 "读取软件版本使能位_IMM10";
CM_ SG_ 2332109482 Reserved_26 "预留预留";
CM_ SG_ 2332109482 M2I_Byrack_IsPostTm_IMM10_26 "绝缘采样时间_IMM10";
CM_ SG_ 2332109482 M2I_Byrack_SysABStTm_IMM10_26 "电压稳定时间_IMM10";
CM_ SG_ 2332109483 CRC_M2I_Byrack_IMM10_27 "CRC校验_IMM10";
CM_ SG_ 2332109483 M2I_Byrack_HVS_IMM10_27 "绝缘测量电压_IMM10";
CM_ SG_ 2332109483 M2I_Byrack_Enable_IMM10_27 "绝缘采样使能位_IMM10";
CM_ SG_ 2332109483 M2I_Byrack_ReVeEnable_IMM10_27 "读取软件版本使能位_IMM10";
CM_ SG_ 2332109483 Reserved_27 "预留预留";
CM_ SG_ 2332109483 M2I_Byrack_IsPostTm_IMM10_27 "绝缘采样时间_IMM10";
CM_ SG_ 2332109483 M2I_Byrack_SysABStTm_IMM10_27 "电压稳定时间_IMM10";
VAL_ 2332108191 M2I_Byrack_Enable_IMM5_15 1 "Deactive" 2 "Active" ;
VAL_ 2332108191 M2I_Byrack_ReVeEnable_IMM5_15 0 "invalid" 1 "Read SW-Version" 2 "Read HW-Version" 3 "Barcode" ;
VAL_ 2332108192 M2I_Byrack_Enable_IMM5_16 1 "Deactive" 2 "Active" ;
VAL_ 2332108192 M2I_Byrack_ReVeEnable_IMM5_16 0 "invalid" 1 "Read SW-Version" 2 "Read HW-Version" 3 "Barcode" ;
VAL_ 2332108193 M2I_Byrack_Enable_IMM5_17 1 "Deactive" 2 "Active" ;
VAL_ 2332108193 M2I_Byrack_ReVeEnable_IMM5_17 0 "invalid" 1 "Read SW-Version" 2 "Read HW-Version" 3 "Barcode" ;
VAL_ 2332108194 M2I_Byrack_Enable_IMM5_18 1 "Deactive" 2 "Active" ;
VAL_ 2332108194 M2I_Byrack_ReVeEnable_IMM5_18 0 "invalid" 1 "Read SW-Version" 2 "Read HW-Version" 3 "Barcode" ;
VAL_ 2332108195 M2I_Byrack_Enable_IMM5_19 1 "Deactive" 2 "Active" ;
VAL_ 2332108195 M2I_Byrack_ReVeEnable_IMM5_19 0 "invalid" 1 "Read SW-Version" 2 "Read HW-Version" 3 "Barcode" ;
VAL_ 2332108196 M2I_Byrack_Enable_IMM5_20 1 "Deactive" 2 "Active" ;
VAL_ 2332108196 M2I_Byrack_ReVeEnable_IMM5_20 0 "invalid" 1 "Read SW-Version" 2 "Read HW-Version" 3 "Barcode" ;
VAL_ 2332108197 M2I_Byrack_Enable_IMM5_21 1 "Deactive" 2 "Active" ;
VAL_ 2332108197 M2I_Byrack_ReVeEnable_IMM5_21 0 "invalid" 1 "Read SW-Version" 2 "Read HW-Version" 3 "Barcode" ;
VAL_ 2332108198 M2I_Byrack_Enable_IMM5_22 1 "Deactive" 2 "Active" ;
VAL_ 2332108198 M2I_Byrack_ReVeEnable_IMM5_22 0 "invalid" 1 "Read SW-Version" 2 "Read HW-Version" 3 "Barcode" ;
VAL_ 2332108199 M2I_Byrack_Enable_IMM5_23 1 "Deactive" 2 "Active" ;
VAL_ 2332108199 M2I_Byrack_ReVeEnable_IMM5_23 0 "invalid" 1 "Read SW-Version" 2 "Read HW-Version" 3 "Barcode" ;
VAL_ 2332108200 M2I_Byrack_Enable_IMM5_24 1 "Deactive" 2 "Active" ;
VAL_ 2332108200 M2I_Byrack_ReVeEnable_IMM5_24 0 "invalid" 1 "Read SW-Version" 2 "Read HW-Version" 3 "Barcode" ;
VAL_ 2332108201 M2I_Byrack_Enable_IMM5_25 1 "Deactive" 2 "Active" ;
VAL_ 2332108201 M2I_Byrack_ReVeEnable_IMM5_25 0 "invalid" 1 "Read SW-Version" 2 "Read HW-Version" 3 "Barcode" ;
VAL_ 2332108202 M2I_Byrack_Enable_IMM5_26 1 "Deactive" 2 "Active" ;
VAL_ 2332108202 M2I_Byrack_ReVeEnable_IMM5_26 0 "invalid" 1 "Read SW-Version" 2 "Read HW-Version" 3 "Barcode" ;
VAL_ 2332108203 M2I_Byrack_Enable_IMM5_27 1 "Deactive" 2 "Active" ;
VAL_ 2332108203 M2I_Byrack_ReVeEnable_IMM5_27 0 "invalid" 1 "Read SW-Version" 2 "Read HW-Version" 3 "Barcode" ;
VAL_ 2332108204 M2I_Byrack_Enable_IMM5_28 1 "Deactive" 2 "Active" ;
VAL_ 2332108204 M2I_Byrack_ReVeEnable_IMM5_28 0 "invalid" 1 "Read SW-Version" 2 "Read HW-Version" 3 "Barcode" ;
VAL_ 2332108205 M2I_Byrack_Enable_IMM5_29 1 "Deactive" 2 "Active" ;
VAL_ 2332108205 M2I_Byrack_ReVeEnable_IMM5_29 0 "invalid" 1 "Read SW-Version" 2 "Read HW-Version" 3 "Barcode" ;
VAL_ 2332108206 M2I_Byrack_Enable_IMM5_30 1 "Deactive" 2 "Active" ;
VAL_ 2332108206 M2I_Byrack_ReVeEnable_IMM5_30 0 "invalid" 1 "Read SW-Version" 2 "Read HW-Version" 3 "Barcode" ;
VAL_ 2332108207 M2I_Byrack_Enable_IMM5_31 1 "Deactive" 2 "Active" ;
VAL_ 2332108207 M2I_Byrack_ReVeEnable_IMM5_31 0 "invalid" 1 "Read SW-Version" 2 "Read HW-Version" 3 "Barcode" ;
VAL_ 2332108433 M2I_Byrack_Enable_IMM6_01 1 "Deactive" 2 "Active" ;
VAL_ 2332108433 M2I_Byrack_ReVeEnable_IMM6_01 0 "invalid" 1 "Read SW-Version" 2 "Read HW-Version" 3 "Barcode" ;
VAL_ 2332108434 M2I_Byrack_Enable_IMM6_02 1 "Deactive" 2 "Active" ;
VAL_ 2332108434 M2I_Byrack_ReVeEnable_IMM6_02 0 "invalid" 1 "Read SW-Version" 2 "Read HW-Version" 3 "Barcode" ;
VAL_ 2332108435 M2I_Byrack_Enable_IMM6_03 1 "Deactive" 2 "Active" ;
VAL_ 2332108435 M2I_Byrack_ReVeEnable_IMM6_03 0 "invalid" 1 "Read SW-Version" 2 "Read HW-Version" 3 "Barcode" ;
VAL_ 2332108436 M2I_Byrack_Enable_IMM6_04 1 "Deactive" 2 "Active" ;
VAL_ 2332108436 M2I_Byrack_ReVeEnable_IMM6_04 0 "invalid" 1 "Read SW-Version" 2 "Read HW-Version" 3 "Barcode" ;
VAL_ 2332108437 M2I_Byrack_Enable_IMM6_05 1 "Deactive" 2 "Active" ;
VAL_ 2332108437 M2I_Byrack_ReVeEnable_IMM6_05 0 "invalid" 1 "Read SW-Version" 2 "Read HW-Version" 3 "Barcode" ;
VAL_ 2332108438 M2I_Byrack_Enable_IMM6_06 1 "Deactive" 2 "Active" ;
VAL_ 2332108438 M2I_Byrack_ReVeEnable_IMM6_06 0 "invalid" 1 "Read SW-Version" 2 "Read HW-Version" 3 "Barcode" ;
VAL_ 2332108439 M2I_Byrack_Enable_IMM6_07 1 "Deactive" 2 "Active" ;
VAL_ 2332108439 M2I_Byrack_ReVeEnable_IMM6_07 0 "invalid" 1 "Read SW-Version" 2 "Read HW-Version" 3 "Barcode" ;
VAL_ 2332108440 M2I_Byrack_Enable_IMM6_08 1 "Deactive" 2 "Active" ;
VAL_ 2332108440 M2I_Byrack_ReVeEnable_IMM6_08 0 "invalid" 1 "Read SW-Version" 2 "Read HW-Version" 3 "Barcode" ;
VAL_ 2332108441 M2I_Byrack_Enable_IMM6_09 1 "Deactive" 2 "Active" ;
VAL_ 2332108441 M2I_Byrack_ReVeEnable_IMM6_09 0 "invalid" 1 "Read SW-Version" 2 "Read HW-Version" 3 "Barcode" ;
VAL_ 2332108442 M2I_Byrack_Enable_IMM6_10 1 "Deactive" 2 "Active" ;
VAL_ 2332108442 M2I_Byrack_ReVeEnable_IMM6_10 0 "invalid" 1 "Read SW-Version" 2 "Read HW-Version" 3 "Barcode" ;
VAL_ 2332108443 M2I_Byrack_Enable_IMM6_11 1 "Deactive" 2 "Active" ;
VAL_ 2332108443 M2I_Byrack_ReVeEnable_IMM6_11 0 "invalid" 1 "Read SW-Version" 2 "Read HW-Version" 3 "Barcode" ;
VAL_ 2332108444 M2I_Byrack_Enable_IMM6_12 1 "Deactive" 2 "Active" ;
VAL_ 2332108444 M2I_Byrack_ReVeEnable_IMM6_12 0 "invalid" 1 "Read SW-Version" 2 "Read HW-Version" 3 "Barcode" ;
VAL_ 2332108445 M2I_Byrack_Enable_IMM6_13 1 "Deactive" 2 "Active" ;
VAL_ 2332108445 M2I_Byrack_ReVeEnable_IMM6_13 0 "invalid" 1 "Read SW-Version" 2 "Read HW-Version" 3 "Barcode" ;
VAL_ 2332108446 M2I_Byrack_Enable_IMM6_14 1 "Deactive" 2 "Active" ;
VAL_ 2332108446 M2I_Byrack_ReVeEnable_IMM6_14 0 "invalid" 1 "Read SW-Version" 2 "Read HW-Version" 3 "Barcode" ;
VAL_ 2332108447 M2I_Byrack_Enable_IMM6_15 1 "Deactive" 2 "Active" ;
VAL_ 2332108447 M2I_Byrack_ReVeEnable_IMM6_15 0 "invalid" 1 "Read SW-Version" 2 "Read HW-Version" 3 "Barcode" ;
VAL_ 2332108448 M2I_Byrack_Enable_IMM6_16 1 "Deactive" 2 "Active" ;
VAL_ 2332108448 M2I_Byrack_ReVeEnable_IMM6_16 0 "invalid" 1 "Read SW-Version" 2 "Read HW-Version" 3 "Barcode" ;
VAL_ 2332108449 M2I_Byrack_Enable_IMM6_17 1 "Deactive" 2 "Active" ;
VAL_ 2332108449 M2I_Byrack_ReVeEnable_IMM6_17 0 "invalid" 1 "Read SW-Version" 2 "Read HW-Version" 3 "Barcode" ;
VAL_ 2332108450 M2I_Byrack_Enable_IMM6_18 1 "Deactive" 2 "Active" ;
VAL_ 2332108450 M2I_Byrack_ReVeEnable_IMM6_18 0 "invalid" 1 "Read SW-Version" 2 "Read HW-Version" 3 "Barcode" ;
VAL_ 2332108451 M2I_Byrack_Enable_IMM6_19 1 "Deactive" 2 "Active" ;
VAL_ 2332108451 M2I_Byrack_ReVeEnable_IMM6_19 0 "invalid" 1 "Read SW-Version" 2 "Read HW-Version" 3 "Barcode" ;
VAL_ 2332108452 M2I_Byrack_Enable_IMM6_20 1 "Deactive" 2 "Active" ;
VAL_ 2332108452 M2I_Byrack_ReVeEnable_IMM6_20 0 "invalid" 1 "Read SW-Version" 2 "Read HW-Version" 3 "Barcode" ;
VAL_ 2332108453 M2I_Byrack_Enable_IMM6_21 1 "Deactive" 2 "Active" ;
VAL_ 2332108453 M2I_Byrack_ReVeEnable_IMM6_21 0 "invalid" 1 "Read SW-Version" 2 "Read HW-Version" 3 "Barcode" ;
VAL_ 2332108454 M2I_Byrack_Enable_IMM6_22 1 "Deactive" 2 "Active" ;
VAL_ 2332108454 M2I_Byrack_ReVeEnable_IMM6_22 0 "invalid" 1 "Read SW-Version" 2 "Read HW-Version" 3 "Barcode" ;
VAL_ 2332108455 M2I_Byrack_Enable_IMM6_23 1 "Deactive" 2 "Active" ;
VAL_ 2332108455 M2I_Byrack_ReVeEnable_IMM6_23 0 "invalid" 1 "Read SW-Version" 2 "Read HW-Version" 3 "Barcode" ;
VAL_ 2332108456 M2I_Byrack_Enable_IMM6_24 1 "Deactive" 2 "Active" ;
VAL_ 2332108456 M2I_Byrack_ReVeEnable_IMM6_24 0 "invalid" 1 "Read SW-Version" 2 "Read HW-Version" 3 "Barcode" ;
VAL_ 2332108457 M2I_Byrack_Enable_IMM6_25 1 "Deactive" 2 "Active" ;
VAL_ 2332108457 M2I_Byrack_ReVeEnable_IMM6_25 0 "invalid" 1 "Read SW-Version" 2 "Read HW-Version" 3 "Barcode" ;
VAL_ 2332108458 M2I_Byrack_Enable_IMM6_26 1 "Deactive" 2 "Active" ;
VAL_ 2332108458 M2I_Byrack_ReVeEnable_IMM6_26 0 "invalid" 1 "Read SW-Version" 2 "Read HW-Version" 3 "Barcode" ;
VAL_ 2332108459 M2I_Byrack_Enable_IMM6_27 1 "Deactive" 2 "Active" ;
VAL_ 2332108459 M2I_Byrack_ReVeEnable_IMM6_27 0 "invalid" 1 "Read SW-Version" 2 "Read HW-Version" 3 "Barcode" ;
VAL_ 2332108460 M2I_Byrack_Enable_IMM6_28 1 "Deactive" 2 "Active" ;
VAL_ 2332108460 M2I_Byrack_ReVeEnable_IMM6_28 0 "invalid" 1 "Read SW-Version" 2 "Read HW-Version" 3 "Barcode" ;
VAL_ 2332108461 M2I_Byrack_Enable_IMM6_29 1 "Deactive" 2 "Active" ;
VAL_ 2332108461 M2I_Byrack_ReVeEnable_IMM6_29 0 "invalid" 1 "Read SW-Version" 2 "Read HW-Version" 3 "Barcode" ;
VAL_ 2332108462 M2I_Byrack_Enable_IMM6_30 1 "Deactive" 2 "Active" ;
VAL_ 2332108462 M2I_Byrack_ReVeEnable_IMM6_30 0 "invalid" 1 "Read SW-Version" 2 "Read HW-Version" 3 "Barcode" ;
VAL_ 2332108463 M2I_Byrack_Enable_IMM6_31 1 "Deactive" 2 "Active" ;
VAL_ 2332108463 M2I_Byrack_ReVeEnable_IMM6_31 0 "invalid" 1 "Read SW-Version" 2 "Read HW-Version" 3 "Barcode" ;
VAL_ 2332108689 M2I_Byrack_Enable_IMM7_01 1 "Deactive" 2 "Active" ;
VAL_ 2332108689 M2I_Byrack_ReVeEnable_IMM7_01 0 "invalid" 1 "Read SW-Version" 2 "Read HW-Version" 3 "Barcode" ;
VAL_ 2332108690 M2I_Byrack_Enable_IMM7_02 1 "Deactive" 2 "Active" ;
VAL_ 2332108690 M2I_Byrack_ReVeEnable_IMM7_02 0 "invalid" 1 "Read SW-Version" 2 "Read HW-Version" 3 "Barcode" ;
VAL_ 2332108691 M2I_Byrack_Enable_IMM7_03 1 "Deactive" 2 "Active" ;
VAL_ 2332108691 M2I_Byrack_ReVeEnable_IMM7_03 0 "invalid" 1 "Read SW-Version" 2 "Read HW-Version" 3 "Barcode" ;
VAL_ 2332108692 M2I_Byrack_Enable_IMM7_04 1 "Deactive" 2 "Active" ;
VAL_ 2332108692 M2I_Byrack_ReVeEnable_IMM7_04 0 "invalid" 1 "Read SW-Version" 2 "Read HW-Version" 3 "Barcode" ;
VAL_ 2332108693 M2I_Byrack_Enable_IMM7_05 1 "Deactive" 2 "Active" ;
VAL_ 2332108693 M2I_Byrack_ReVeEnable_IMM7_05 0 "invalid" 1 "Read SW-Version" 2 "Read HW-Version" 3 "Barcode" ;
VAL_ 2332108694 M2I_Byrack_Enable_IMM7_06 1 "Deactive" 2 "Active" ;
VAL_ 2332108694 M2I_Byrack_ReVeEnable_IMM7_06 0 "invalid" 1 "Read SW-Version" 2 "Read HW-Version" 3 "Barcode" ;
VAL_ 2332108695 M2I_Byrack_Enable_IMM7_07 1 "Deactive" 2 "Active" ;
VAL_ 2332108695 M2I_Byrack_ReVeEnable_IMM7_07 0 "invalid" 1 "Read SW-Version" 2 "Read HW-Version" 3 "Barcode" ;
VAL_ 2332108696 M2I_Byrack_Enable_IMM7_08 1 "Deactive" 2 "Active" ;
VAL_ 2332108696 M2I_Byrack_ReVeEnable_IMM7_08 0 "invalid" 1 "Read SW-Version" 2 "Read HW-Version" 3 "Barcode" ;
VAL_ 2332108697 M2I_Byrack_Enable_IMM7_09 1 "Deactive" 2 "Active" ;
VAL_ 2332108697 M2I_Byrack_ReVeEnable_IMM7_09 0 "invalid" 1 "Read SW-Version" 2 "Read HW-Version" 3 "Barcode" ;
VAL_ 2332108698 M2I_Byrack_Enable_IMM7_10 1 "Deactive" 2 "Active" ;
VAL_ 2332108698 M2I_Byrack_ReVeEnable_IMM7_10 0 "invalid" 1 "Read SW-Version" 2 "Read HW-Version" 3 "Barcode" ;
VAL_ 2332108699 M2I_Byrack_Enable_IMM7_11 1 "Deactive" 2 "Active" ;
VAL_ 2332108699 M2I_Byrack_ReVeEnable_IMM7_11 0 "invalid" 1 "Read SW-Version" 2 "Read HW-Version" 3 "Barcode" ;
VAL_ 2332108700 M2I_Byrack_Enable_IMM7_12 1 "Deactive" 2 "Active" ;
VAL_ 2332108700 M2I_Byrack_ReVeEnable_IMM7_12 0 "invalid" 1 "Read SW-Version" 2 "Read HW-Version" 3 "Barcode" ;
VAL_ 2332108701 M2I_Byrack_Enable_IMM7_13 1 "Deactive" 2 "Active" ;
VAL_ 2332108701 M2I_Byrack_ReVeEnable_IMM7_13 0 "invalid" 1 "Read SW-Version" 2 "Read HW-Version" 3 "Barcode" ;
VAL_ 2332108702 M2I_Byrack_Enable_IMM7_14 1 "Deactive" 2 "Active" ;
VAL_ 2332108702 M2I_Byrack_ReVeEnable_IMM7_14 0 "invalid" 1 "Read SW-Version" 2 "Read HW-Version" 3 "Barcode" ;
VAL_ 2332108703 M2I_Byrack_Enable_IMM7_15 1 "Deactive" 2 "Active" ;
VAL_ 2332108703 M2I_Byrack_ReVeEnable_IMM7_15 0 "invalid" 1 "Read SW-Version" 2 "Read HW-Version" 3 "Barcode" ;
VAL_ 2332108704 M2I_Byrack_Enable_IMM7_16 1 "Deactive" 2 "Active" ;
VAL_ 2332108704 M2I_Byrack_ReVeEnable_IMM7_16 0 "invalid" 1 "Read SW-Version" 2 "Read HW-Version" 3 "Barcode" ;
VAL_ 2332108705 M2I_Byrack_Enable_IMM7_17 1 "Deactive" 2 "Active" ;
VAL_ 2332108705 M2I_Byrack_ReVeEnable_IMM7_17 0 "invalid" 1 "Read SW-Version" 2 "Read HW-Version" 3 "Barcode" ;
VAL_ 2332108706 M2I_Byrack_Enable_IMM7_18 1 "Deactive" 2 "Active" ;
VAL_ 2332108706 M2I_Byrack_ReVeEnable_IMM7_18 0 "invalid" 1 "Read SW-Version" 2 "Read HW-Version" 3 "Barcode" ;
VAL_ 2332108707 M2I_Byrack_Enable_IMM7_19 1 "Deactive" 2 "Active" ;
VAL_ 2332108707 M2I_Byrack_ReVeEnable_IMM7_19 0 "invalid" 1 "Read SW-Version" 2 "Read HW-Version" 3 "Barcode" ;
VAL_ 2332108708 M2I_Byrack_Enable_IMM7_20 1 "Deactive" 2 "Active" ;
VAL_ 2332108708 M2I_Byrack_ReVeEnable_IMM7_20 0 "invalid" 1 "Read SW-Version" 2 "Read HW-Version" 3 "Barcode" ;
VAL_ 2332108709 M2I_Byrack_Enable_IMM7_21 1 "Deactive" 2 "Active" ;
VAL_ 2332108709 M2I_Byrack_ReVeEnable_IMM7_21 0 "invalid" 1 "Read SW-Version" 2 "Read HW-Version" 3 "Barcode" ;
VAL_ 2332108710 M2I_Byrack_Enable_IMM7_22 1 "Deactive" 2 "Active" ;
VAL_ 2332108710 M2I_Byrack_ReVeEnable_IMM7_22 0 "invalid" 1 "Read SW-Version" 2 "Read HW-Version" 3 "Barcode" ;
VAL_ 2332108711 M2I_Byrack_Enable_IMM7_23 1 "Deactive" 2 "Active" ;
VAL_ 2332108711 M2I_Byrack_ReVeEnable_IMM7_23 0 "invalid" 1 "Read SW-Version" 2 "Read HW-Version" 3 "Barcode" ;
VAL_ 2332108712 M2I_Byrack_Enable_IMM7_24 1 "Deactive" 2 "Active" ;
VAL_ 2332108712 M2I_Byrack_ReVeEnable_IMM7_24 0 "invalid" 1 "Read SW-Version" 2 "Read HW-Version" 3 "Barcode" ;
VAL_ 2332108713 M2I_Byrack_Enable_IMM7_25 1 "Deactive" 2 "Active" ;
VAL_ 2332108713 M2I_Byrack_ReVeEnable_IMM7_25 0 "invalid" 1 "Read SW-Version" 2 "Read HW-Version" 3 "Barcode" ;
VAL_ 2332108714 M2I_Byrack_Enable_IMM7_26 1 "Deactive" 2 "Active" ;
VAL_ 2332108714 M2I_Byrack_ReVeEnable_IMM7_26 0 "invalid" 1 "Read SW-Version" 2 "Read HW-Version" 3 "Barcode" ;
VAL_ 2332108715 M2I_Byrack_Enable_IMM7_27 1 "Deactive" 2 "Active" ;
VAL_ 2332108715 M2I_Byrack_ReVeEnable_IMM7_27 0 "invalid" 1 "Read SW-Version" 2 "Read HW-Version" 3 "Barcode" ;
VAL_ 2332108716 M2I_Byrack_Enable_IMM7_28 1 "Deactive" 2 "Active" ;
VAL_ 2332108716 M2I_Byrack_ReVeEnable_IMM7_28 0 "invalid" 1 "Read SW-Version" 2 "Read HW-Version" 3 "Barcode" ;
VAL_ 2332108717 M2I_Byrack_Enable_IMM7_29 1 "Deactive" 2 "Active" ;
VAL_ 2332108717 M2I_Byrack_ReVeEnable_IMM7_29 0 "invalid" 1 "Read SW-Version" 2 "Read HW-Version" 3 "Barcode" ;
VAL_ 2332108718 M2I_Byrack_Enable_IMM7_30 1 "Deactive" 2 "Active" ;
VAL_ 2332108718 M2I_Byrack_ReVeEnable_IMM7_30 0 "invalid" 1 "Read SW-Version" 2 "Read HW-Version" 3 "Barcode" ;
VAL_ 2332108719 M2I_Byrack_Enable_IMM7_31 1 "Deactive" 2 "Active" ;
VAL_ 2332108719 M2I_Byrack_ReVeEnable_IMM7_31 0 "invalid" 1 "Read SW-Version" 2 "Read HW-Version" 3 "Barcode" ;
VAL_ 2332108945 M2I_Byrack_Enable_IMM8_01 1 "Deactive" 2 "Active" ;
VAL_ 2332108945 M2I_Byrack_ReVeEnable_IMM8_01 0 "invalid" 1 "Read SW-Version" 2 "Read HW-Version" 3 "Barcode" ;
VAL_ 2332108946 M2I_Byrack_Enable_IMM8_02 1 "Deactive" 2 "Active" ;
VAL_ 2332108946 M2I_Byrack_ReVeEnable_IMM8_02 0 "invalid" 1 "Read SW-Version" 2 "Read HW-Version" 3 "Barcode" ;
VAL_ 2332108947 M2I_Byrack_Enable_IMM8_03 1 "Deactive" 2 "Active" ;
VAL_ 2332108947 M2I_Byrack_ReVeEnable_IMM8_03 0 "invalid" 1 "Read SW-Version" 2 "Read HW-Version" 3 "Barcode" ;
VAL_ 2332108948 M2I_Byrack_Enable_IMM8_04 1 "Deactive" 2 "Active" ;
VAL_ 2332108948 M2I_Byrack_ReVeEnable_IMM8_04 0 "invalid" 1 "Read SW-Version" 2 "Read HW-Version" 3 "Barcode" ;
VAL_ 2332108949 M2I_Byrack_Enable_IMM8_05 1 "Deactive" 2 "Active" ;
VAL_ 2332108949 M2I_Byrack_ReVeEnable_IMM8_05 0 "invalid" 1 "Read SW-Version" 2 "Read HW-Version" 3 "Barcode" ;
VAL_ 2332108950 M2I_Byrack_Enable_IMM8_06 1 "Deactive" 2 "Active" ;
VAL_ 2332108950 M2I_Byrack_ReVeEnable_IMM8_06 0 "invalid" 1 "Read SW-Version" 2 "Read HW-Version" 3 "Barcode" ;
VAL_ 2332108951 M2I_Byrack_Enable_IMM8_07 1 "Deactive" 2 "Active" ;
VAL_ 2332108951 M2I_Byrack_ReVeEnable_IMM8_07 0 "invalid" 1 "Read SW-Version" 2 "Read HW-Version" 3 "Barcode" ;
VAL_ 2332108952 M2I_Byrack_Enable_IMM8_08 1 "Deactive" 2 "Active" ;
VAL_ 2332108952 M2I_Byrack_ReVeEnable_IMM8_08 0 "invalid" 1 "Read SW-Version" 2 "Read HW-Version" 3 "Barcode" ;
VAL_ 2332108953 M2I_Byrack_Enable_IMM8_09 1 "Deactive" 2 "Active" ;
VAL_ 2332108953 M2I_Byrack_ReVeEnable_IMM8_09 0 "invalid" 1 "Read SW-Version" 2 "Read HW-Version" 3 "Barcode" ;
VAL_ 2332108954 M2I_Byrack_Enable_IMM8_10 1 "Deactive" 2 "Active" ;
VAL_ 2332108954 M2I_Byrack_ReVeEnable_IMM8_10 0 "invalid" 1 "Read SW-Version" 2 "Read HW-Version" 3 "Barcode" ;
VAL_ 2332108955 M2I_Byrack_Enable_IMM8_11 1 "Deactive" 2 "Active" ;
VAL_ 2332108955 M2I_Byrack_ReVeEnable_IMM8_11 0 "invalid" 1 "Read SW-Version" 2 "Read HW-Version" 3 "Barcode" ;
VAL_ 2332108956 M2I_Byrack_Enable_IMM8_12 1 "Deactive" 2 "Active" ;
VAL_ 2332108956 M2I_Byrack_ReVeEnable_IMM8_12 0 "invalid" 1 "Read SW-Version" 2 "Read HW-Version" 3 "Barcode" ;
VAL_ 2332108957 M2I_Byrack_Enable_IMM8_13 1 "Deactive" 2 "Active" ;
VAL_ 2332108957 M2I_Byrack_ReVeEnable_IMM8_13 0 "invalid" 1 "Read SW-Version" 2 "Read HW-Version" 3 "Barcode" ;
VAL_ 2332108958 M2I_Byrack_Enable_IMM8_14 1 "Deactive" 2 "Active" ;
VAL_ 2332108958 M2I_Byrack_ReVeEnable_IMM8_14 0 "invalid" 1 "Read SW-Version" 2 "Read HW-Version" 3 "Barcode" ;
VAL_ 2332108959 M2I_Byrack_Enable_IMM8_15 1 "Deactive" 2 "Active" ;
VAL_ 2332108959 M2I_Byrack_ReVeEnable_IMM8_15 0 "invalid" 1 "Read SW-Version" 2 "Read HW-Version" 3 "Barcode" ;
VAL_ 2332108960 M2I_Byrack_Enable_IMM8_16 1 "Deactive" 2 "Active" ;
VAL_ 2332108960 M2I_Byrack_ReVeEnable_IMM8_16 0 "invalid" 1 "Read SW-Version" 2 "Read HW-Version" 3 "Barcode" ;
VAL_ 2332108961 M2I_Byrack_Enable_IMM8_17 1 "Deactive" 2 "Active" ;
VAL_ 2332108961 M2I_Byrack_ReVeEnable_IMM8_17 0 "invalid" 1 "Read SW-Version" 2 "Read HW-Version" 3 "Barcode" ;
VAL_ 2332108962 M2I_Byrack_Enable_IMM8_18 1 "Deactive" 2 "Active" ;
VAL_ 2332108962 M2I_Byrack_ReVeEnable_IMM8_18 0 "invalid" 1 "Read SW-Version" 2 "Read HW-Version" 3 "Barcode" ;
VAL_ 2332108963 M2I_Byrack_Enable_IMM8_19 1 "Deactive" 2 "Active" ;
VAL_ 2332108963 M2I_Byrack_ReVeEnable_IMM8_19 0 "invalid" 1 "Read SW-Version" 2 "Read HW-Version" 3 "Barcode" ;
VAL_ 2332108964 M2I_Byrack_Enable_IMM8_20 1 "Deactive" 2 "Active" ;
VAL_ 2332108964 M2I_Byrack_ReVeEnable_IMM8_20 0 "invalid" 1 "Read SW-Version" 2 "Read HW-Version" 3 "Barcode" ;
VAL_ 2332108965 M2I_Byrack_Enable_IMM8_21 1 "Deactive" 2 "Active" ;
VAL_ 2332108965 M2I_Byrack_ReVeEnable_IMM8_21 0 "invalid" 1 "Read SW-Version" 2 "Read HW-Version" 3 "Barcode" ;
VAL_ 2332108966 M2I_Byrack_Enable_IMM8_22 1 "Deactive" 2 "Active" ;
VAL_ 2332108966 M2I_Byrack_ReVeEnable_IMM8_22 0 "invalid" 1 "Read SW-Version" 2 "Read HW-Version" 3 "Barcode" ;
VAL_ 2332108967 M2I_Byrack_Enable_IMM8_23 1 "Deactive" 2 "Active" ;
VAL_ 2332108967 M2I_Byrack_ReVeEnable_IMM8_23 0 "invalid" 1 "Read SW-Version" 2 "Read HW-Version" 3 "Barcode" ;
VAL_ 2332108968 M2I_Byrack_Enable_IMM8_24 1 "Deactive" 2 "Active" ;
VAL_ 2332108968 M2I_Byrack_ReVeEnable_IMM8_24 0 "invalid" 1 "Read SW-Version" 2 "Read HW-Version" 3 "Barcode" ;
VAL_ 2332108969 M2I_Byrack_Enable_IMM8_25 1 "Deactive" 2 "Active" ;
VAL_ 2332108969 M2I_Byrack_ReVeEnable_IMM8_25 0 "invalid" 1 "Read SW-Version" 2 "Read HW-Version" 3 "Barcode" ;
VAL_ 2332108970 M2I_Byrack_Enable_IMM8_26 1 "Deactive" 2 "Active" ;
VAL_ 2332108970 M2I_Byrack_ReVeEnable_IMM8_26 0 "invalid" 1 "Read SW-Version" 2 "Read HW-Version" 3 "Barcode" ;
VAL_ 2332108971 M2I_Byrack_Enable_IMM8_27 1 "Deactive" 2 "Active" ;
VAL_ 2332108971 M2I_Byrack_ReVeEnable_IMM8_27 0 "invalid" 1 "Read SW-Version" 2 "Read HW-Version" 3 "Barcode" ;
VAL_ 2332108972 M2I_Byrack_Enable_IMM8_28 1 "Deactive" 2 "Active" ;
VAL_ 2332108972 M2I_Byrack_ReVeEnable_IMM8_28 0 "invalid" 1 "Read SW-Version" 2 "Read HW-Version" 3 "Barcode" ;
VAL_ 2332108973 M2I_Byrack_Enable_IMM8_29 1 "Deactive" 2 "Active" ;
VAL_ 2332108973 M2I_Byrack_ReVeEnable_IMM8_29 0 "invalid" 1 "Read SW-Version" 2 "Read HW-Version" 3 "Barcode" ;
VAL_ 2332108974 M2I_Byrack_Enable_IMM8_30 1 "Deactive" 2 "Active" ;
VAL_ 2332108974 M2I_Byrack_ReVeEnable_IMM8_30 0 "invalid" 1 "Read SW-Version" 2 "Read HW-Version" 3 "Barcode" ;
VAL_ 2332108975 M2I_Byrack_Enable_IMM8_31 1 "Deactive" 2 "Active" ;
VAL_ 2332108975 M2I_Byrack_ReVeEnable_IMM8_31 0 "invalid" 1 "Read SW-Version" 2 "Read HW-Version" 3 "Barcode" ;
VAL_ 2332109201 M2I_Byrack_Enable_IMM9_01 1 "Deactive" 2 "Active" ;
VAL_ 2332109201 M2I_Byrack_ReVeEnable_IMM9_01 0 "invalid" 1 "Read SW-Version" 2 "Read HW-Version" 3 "Barcode" ;
VAL_ 2332109202 M2I_Byrack_Enable_IMM9_02 1 "Deactive" 2 "Active" ;
VAL_ 2332109202 M2I_Byrack_ReVeEnable_IMM9_02 0 "invalid" 1 "Read SW-Version" 2 "Read HW-Version" 3 "Barcode" ;
VAL_ 2332109203 M2I_Byrack_Enable_IMM9_03 1 "Deactive" 2 "Active" ;
VAL_ 2332109203 M2I_Byrack_ReVeEnable_IMM9_03 0 "invalid" 1 "Read SW-Version" 2 "Read HW-Version" 3 "Barcode" ;
VAL_ 2332109204 M2I_Byrack_Enable_IMM9_04 1 "Deactive" 2 "Active" ;
VAL_ 2332109204 M2I_Byrack_ReVeEnable_IMM9_04 0 "invalid" 1 "Read SW-Version" 2 "Read HW-Version" 3 "Barcode" ;
VAL_ 2332109205 M2I_Byrack_Enable_IMM9_05 1 "Deactive" 2 "Active" ;
VAL_ 2332109205 M2I_Byrack_ReVeEnable_IMM9_05 0 "invalid" 1 "Read SW-Version" 2 "Read HW-Version" 3 "Barcode" ;
VAL_ 2332109206 M2I_Byrack_Enable_IMM9_06 1 "Deactive" 2 "Active" ;
VAL_ 2332109206 M2I_Byrack_ReVeEnable_IMM9_06 0 "invalid" 1 "Read SW-Version" 2 "Read HW-Version" 3 "Barcode" ;
VAL_ 2332109207 M2I_Byrack_Enable_IMM9_07 1 "Deactive" 2 "Active" ;
VAL_ 2332109207 M2I_Byrack_ReVeEnable_IMM9_07 0 "invalid" 1 "Read SW-Version" 2 "Read HW-Version" 3 "Barcode" ;
VAL_ 2332109208 M2I_Byrack_Enable_IMM9_08 1 "Deactive" 2 "Active" ;
VAL_ 2332109208 M2I_Byrack_ReVeEnable_IMM9_08 0 "invalid" 1 "Read SW-Version" 2 "Read HW-Version" 3 "Barcode" ;
VAL_ 2332109209 M2I_Byrack_Enable_IMM9_09 1 "Deactive" 2 "Active" ;
VAL_ 2332109209 M2I_Byrack_ReVeEnable_IMM9_09 0 "invalid" 1 "Read SW-Version" 2 "Read HW-Version" 3 "Barcode" ;
VAL_ 2332109210 M2I_Byrack_Enable_IMM9_10 1 "Deactive" 2 "Active" ;
VAL_ 2332109210 M2I_Byrack_ReVeEnable_IMM9_10 0 "invalid" 1 "Read SW-Version" 2 "Read HW-Version" 3 "Barcode" ;
VAL_ 2332109211 M2I_Byrack_Enable_IMM9_11 1 "Deactive" 2 "Active" ;
VAL_ 2332109211 M2I_Byrack_ReVeEnable_IMM9_11 0 "invalid" 1 "Read SW-Version" 2 "Read HW-Version" 3 "Barcode" ;
VAL_ 2332109212 M2I_Byrack_Enable_IMM9_12 1 "Deactive" 2 "Active" ;
VAL_ 2332109212 M2I_Byrack_ReVeEnable_IMM9_12 0 "invalid" 1 "Read SW-Version" 2 "Read HW-Version" 3 "Barcode" ;
VAL_ 2332109213 M2I_Byrack_Enable_IMM9_13 1 "Deactive" 2 "Active" ;
VAL_ 2332109213 M2I_Byrack_ReVeEnable_IMM9_13 0 "invalid" 1 "Read SW-Version" 2 "Read HW-Version" 3 "Barcode" ;
VAL_ 2332109214 M2I_Byrack_Enable_IMM9_14 1 "Deactive" 2 "Active" ;
VAL_ 2332109214 M2I_Byrack_ReVeEnable_IMM9_14 0 "invalid" 1 "Read SW-Version" 2 "Read HW-Version" 3 "Barcode" ;
VAL_ 2332109215 M2I_Byrack_Enable_IMM9_15 1 "Deactive" 2 "Active" ;
VAL_ 2332109215 M2I_Byrack_ReVeEnable_IMM9_15 0 "invalid" 1 "Read SW-Version" 2 "Read HW-Version" 3 "Barcode" ;
VAL_ 2332109216 M2I_Byrack_Enable_IMM9_16 1 "Deactive" 2 "Active" ;
VAL_ 2332109216 M2I_Byrack_ReVeEnable_IMM9_16 0 "invalid" 1 "Read SW-Version" 2 "Read HW-Version" 3 "Barcode" ;
VAL_ 2332109217 M2I_Byrack_Enable_IMM9_17 1 "Deactive" 2 "Active" ;
VAL_ 2332109217 M2I_Byrack_ReVeEnable_IMM9_17 0 "invalid" 1 "Read SW-Version" 2 "Read HW-Version" 3 "Barcode" ;
VAL_ 2332109218 M2I_Byrack_Enable_IMM9_18 1 "Deactive" 2 "Active" ;
VAL_ 2332109218 M2I_Byrack_ReVeEnable_IMM9_18 0 "invalid" 1 "Read SW-Version" 2 "Read HW-Version" 3 "Barcode" ;
VAL_ 2332109219 M2I_Byrack_Enable_IMM9_19 1 "Deactive" 2 "Active" ;
VAL_ 2332109219 M2I_Byrack_ReVeEnable_IMM9_19 0 "invalid" 1 "Read SW-Version" 2 "Read HW-Version" 3 "Barcode" ;
VAL_ 2332109220 M2I_Byrack_Enable_IMM9_20 1 "Deactive" 2 "Active" ;
VAL_ 2332109220 M2I_Byrack_ReVeEnable_IMM9_20 0 "invalid" 1 "Read SW-Version" 2 "Read HW-Version" 3 "Barcode" ;
VAL_ 2332109221 M2I_Byrack_Enable_IMM9_21 1 "Deactive" 2 "Active" ;
VAL_ 2332109221 M2I_Byrack_ReVeEnable_IMM9_21 0 "invalid" 1 "Read SW-Version" 2 "Read HW-Version" 3 "Barcode" ;
VAL_ 2332109222 M2I_Byrack_Enable_IMM9_22 1 "Deactive" 2 "Active" ;
VAL_ 2332109222 M2I_Byrack_ReVeEnable_IMM9_22 0 "invalid" 1 "Read SW-Version" 2 "Read HW-Version" 3 "Barcode" ;
VAL_ 2332109223 M2I_Byrack_Enable_IMM9_23 1 "Deactive" 2 "Active" ;
VAL_ 2332109223 M2I_Byrack_ReVeEnable_IMM9_23 0 "invalid" 1 "Read SW-Version" 2 "Read HW-Version" 3 "Barcode" ;
VAL_ 2332109224 M2I_Byrack_Enable_IMM9_24 1 "Deactive" 2 "Active" ;
VAL_ 2332109224 M2I_Byrack_ReVeEnable_IMM9_24 0 "invalid" 1 "Read SW-Version" 2 "Read HW-Version" 3 "Barcode" ;
VAL_ 2332109225 M2I_Byrack_Enable_IMM9_25 1 "Deactive" 2 "Active" ;
VAL_ 2332109225 M2I_Byrack_ReVeEnable_IMM9_25 0 "invalid" 1 "Read SW-Version" 2 "Read HW-Version" 3 "Barcode" ;
VAL_ 2332109226 M2I_Byrack_Enable_IMM9_26 1 "Deactive" 2 "Active" ;
VAL_ 2332109226 M2I_Byrack_ReVeEnable_IMM9_26 0 "invalid" 1 "Read SW-Version" 2 "Read HW-Version" 3 "Barcode" ;
VAL_ 2332109227 M2I_Byrack_Enable_IMM9_27 1 "Deactive" 2 "Active" ;
VAL_ 2332109227 M2I_Byrack_ReVeEnable_IMM9_27 0 "invalid" 1 "Read SW-Version" 2 "Read HW-Version" 3 "Barcode" ;
VAL_ 2332109228 M2I_Byrack_Enable_IMM9_28 1 "Deactive" 2 "Active" ;
VAL_ 2332109228 M2I_Byrack_ReVeEnable_IMM9_28 0 "invalid" 1 "Read SW-Version" 2 "Read HW-Version" 3 "Barcode" ;
VAL_ 2332109229 M2I_Byrack_Enable_IMM9_29 1 "Deactive" 2 "Active" ;
VAL_ 2332109229 M2I_Byrack_ReVeEnable_IMM9_29 0 "invalid" 1 "Read SW-Version" 2 "Read HW-Version" 3 "Barcode" ;
VAL_ 2332109230 M2I_Byrack_Enable_IMM9_30 1 "Deactive" 2 "Active" ;
VAL_ 2332109230 M2I_Byrack_ReVeEnable_IMM9_30 0 "invalid" 1 "Read SW-Version" 2 "Read HW-Version" 3 "Barcode" ;
VAL_ 2332109231 M2I_Byrack_Enable_IMM9_31 1 "Deactive" 2 "Active" ;
VAL_ 2332109231 M2I_Byrack_ReVeEnable_IMM9_31 0 "invalid" 1 "Read SW-Version" 2 "Read HW-Version" 3 "Barcode" ;
VAL_ 2332109457 M2I_Byrack_Enable_IMM10_01 1 "Deactive" 2 "Active" ;
VAL_ 2332109457 M2I_Byrack_ReVeEnable_IMM10_01 0 "invalid" 1 "Read SW-Version" 2 "Read HW-Version" 3 "Barcode" ;
VAL_ 2332109458 M2I_Byrack_Enable_IMM10_02 1 "Deactive" 2 "Active" ;
VAL_ 2332109458 M2I_Byrack_ReVeEnable_IMM10_02 0 "invalid" 1 "Read SW-Version" 2 "Read HW-Version" 3 "Barcode" ;
VAL_ 2332109459 M2I_Byrack_Enable_IMM10_03 1 "Deactive" 2 "Active" ;
VAL_ 2332109459 M2I_Byrack_ReVeEnable_IMM10_03 0 "invalid" 1 "Read SW-Version" 2 "Read HW-Version" 3 "Barcode" ;
VAL_ 2332109460 M2I_Byrack_Enable_IMM10_04 1 "Deactive" 2 "Active" ;
VAL_ 2332109460 M2I_Byrack_ReVeEnable_IMM10_04 0 "invalid" 1 "Read SW-Version" 2 "Read HW-Version" 3 "Barcode" ;
VAL_ 2332109461 M2I_Byrack_Enable_IMM10_05 1 "Deactive" 2 "Active" ;
VAL_ 2332109461 M2I_Byrack_ReVeEnable_IMM10_05 0 "invalid" 1 "Read SW-Version" 2 "Read HW-Version" 3 "Barcode" ;
VAL_ 2332109462 M2I_Byrack_Enable_IMM10_06 1 "Deactive" 2 "Active" ;
VAL_ 2332109462 M2I_Byrack_ReVeEnable_IMM10_06 0 "invalid" 1 "Read SW-Version" 2 "Read HW-Version" 3 "Barcode" ;
VAL_ 2332109463 M2I_Byrack_Enable_IMM10_07 1 "Deactive" 2 "Active" ;
VAL_ 2332109463 M2I_Byrack_ReVeEnable_IMM10_07 0 "invalid" 1 "Read SW-Version" 2 "Read HW-Version" 3 "Barcode" ;
VAL_ 2332109464 M2I_Byrack_Enable_IMM10_08 1 "Deactive" 2 "Active" ;
VAL_ 2332109464 M2I_Byrack_ReVeEnable_IMM10_08 0 "invalid" 1 "Read SW-Version" 2 "Read HW-Version" 3 "Barcode" ;
VAL_ 2332109465 M2I_Byrack_Enable_IMM10_09 1 "Deactive" 2 "Active" ;
VAL_ 2332109465 M2I_Byrack_ReVeEnable_IMM10_09 0 "invalid" 1 "Read SW-Version" 2 "Read HW-Version" 3 "Barcode" ;
VAL_ 2332109466 M2I_Byrack_Enable_IMM10_10 1 "Deactive" 2 "Active" ;
VAL_ 2332109466 M2I_Byrack_ReVeEnable_IMM10_10 0 "invalid" 1 "Read SW-Version" 2 "Read HW-Version" 3 "Barcode" ;
VAL_ 2332109467 M2I_Byrack_Enable_IMM10_11 1 "Deactive" 2 "Active" ;
VAL_ 2332109467 M2I_Byrack_ReVeEnable_IMM10_11 0 "invalid" 1 "Read SW-Version" 2 "Read HW-Version" 3 "Barcode" ;
VAL_ 2332109468 M2I_Byrack_Enable_IMM10_12 1 "Deactive" 2 "Active" ;
VAL_ 2332109468 M2I_Byrack_ReVeEnable_IMM10_12 0 "invalid" 1 "Read SW-Version" 2 "Read HW-Version" 3 "Barcode" ;
VAL_ 2332109469 M2I_Byrack_Enable_IMM10_13 1 "Deactive" 2 "Active" ;
VAL_ 2332109469 M2I_Byrack_ReVeEnable_IMM10_13 0 "invalid" 1 "Read SW-Version" 2 "Read HW-Version" 3 "Barcode" ;
VAL_ 2332109470 M2I_Byrack_Enable_IMM10_14 1 "Deactive" 2 "Active" ;
VAL_ 2332109470 M2I_Byrack_ReVeEnable_IMM10_14 0 "invalid" 1 "Read SW-Version" 2 "Read HW-Version" 3 "Barcode" ;
VAL_ 2332109471 M2I_Byrack_Enable_IMM10_15 1 "Deactive" 2 "Active" ;
VAL_ 2332109471 M2I_Byrack_ReVeEnable_IMM10_15 0 "invalid" 1 "Read SW-Version" 2 "Read HW-Version" 3 "Barcode" ;
VAL_ 2332109472 M2I_Byrack_Enable_IMM10_16 1 "Deactive" 2 "Active" ;
VAL_ 2332109472 M2I_Byrack_ReVeEnable_IMM10_16 0 "invalid" 1 "Read SW-Version" 2 "Read HW-Version" 3 "Barcode" ;
VAL_ 2332109473 M2I_Byrack_Enable_IMM10_17 1 "Deactive" 2 "Active" ;
VAL_ 2332109473 M2I_Byrack_ReVeEnable_IMM10_17 0 "invalid" 1 "Read SW-Version" 2 "Read HW-Version" 3 "Barcode" ;
VAL_ 2332109474 M2I_Byrack_Enable_IMM10_18 1 "Deactive" 2 "Active" ;
VAL_ 2332109474 M2I_Byrack_ReVeEnable_IMM10_18 0 "invalid" 1 "Read SW-Version" 2 "Read HW-Version" 3 "Barcode" ;
VAL_ 2332109475 M2I_Byrack_Enable_IMM10_19 1 "Deactive" 2 "Active" ;
VAL_ 2332109475 M2I_Byrack_ReVeEnable_IMM10_19 0 "invalid" 1 "Read SW-Version" 2 "Read HW-Version" 3 "Barcode" ;
VAL_ 2332109476 M2I_Byrack_Enable_IMM10_20 1 "Deactive" 2 "Active" ;
VAL_ 2332109476 M2I_Byrack_ReVeEnable_IMM10_20 0 "invalid" 1 "Read SW-Version" 2 "Read HW-Version" 3 "Barcode" ;
VAL_ 2332109477 M2I_Byrack_Enable_IMM10_21 1 "Deactive" 2 "Active" ;
VAL_ 2332109477 M2I_Byrack_ReVeEnable_IMM10_21 0 "invalid" 1 "Read SW-Version" 2 "Read HW-Version" 3 "Barcode" ;
VAL_ 2332109478 M2I_Byrack_Enable_IMM10_22 1 "Deactive" 2 "Active" ;
VAL_ 2332109478 M2I_Byrack_ReVeEnable_IMM10_22 0 "invalid" 1 "Read SW-Version" 2 "Read HW-Version" 3 "Barcode" ;
VAL_ 2332109479 M2I_Byrack_Enable_IMM10_23 1 "Deactive" 2 "Active" ;
VAL_ 2332109479 M2I_Byrack_ReVeEnable_IMM10_23 0 "invalid" 1 "Read SW-Version" 2 "Read HW-Version" 3 "Barcode" ;
VAL_ 2332109480 M2I_Byrack_Enable_IMM10_24 1 "Deactive" 2 "Active" ;
VAL_ 2332109480 M2I_Byrack_ReVeEnable_IMM10_24 0 "invalid" 1 "Read SW-Version" 2 "Read HW-Version" 3 "Barcode" ;
VAL_ 2332109481 M2I_Byrack_Enable_IMM10_25 1 "Deactive" 2 "Active" ;
VAL_ 2332109481 M2I_Byrack_ReVeEnable_IMM10_25 0 "invalid" 1 "Read SW-Version" 2 "Read HW-Version" 3 "Barcode" ;
VAL_ 2332109482 M2I_Byrack_Enable_IMM10_26 1 "Deactive" 2 "Active" ;
VAL_ 2332109482 M2I_Byrack_ReVeEnable_IMM10_26 0 "invalid" 1 "Read SW-Version" 2 "Read HW-Version" 3 "Barcode" ;
VAL_ 2332109483 M2I_Byrack_Enable_IMM10_27 1 "Deactive" 2 "Active" ;
VAL_ 2332109483 M2I_Byrack_ReVeEnable_IMM10_27 0 "invalid" 1 "Read SW-Version" 2 "Read HW-Version" 3 "Barcode" ;
VERSION ""

NS_ :

BS_:

BU_: MBMU PC SBMU IMM ETH DCDC LEMS

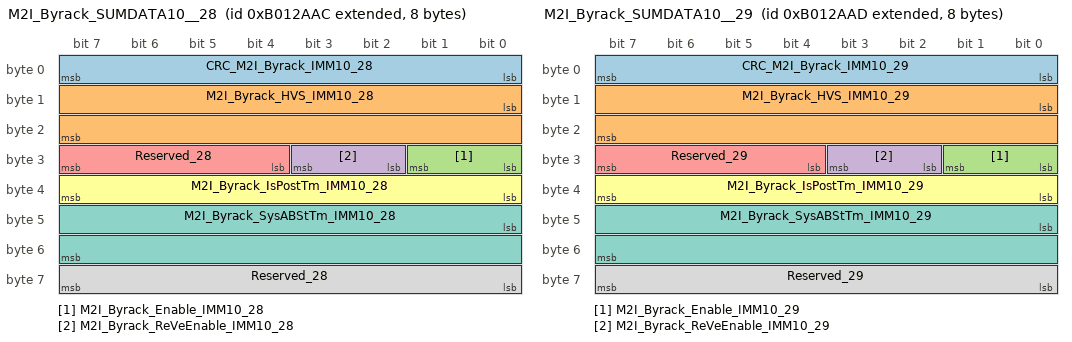
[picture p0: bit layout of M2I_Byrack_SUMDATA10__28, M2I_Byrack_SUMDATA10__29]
BO_ 2332109484 M2I_Byrack_SUMDATA10__28: 8 MBMU
 SG_ CRC_M2I_Byrack_IMM10_28 : 0|8@1+ (1,0) [0|255] ""  IMM
 SG_ M2I_Byrack_HVS_IMM10_28 : 8|16@1+ (0.1,0) [0|6553.5] "v"  IMM
 SG_ M2I_Byrack_Enable_IMM10_28 : 24|2@1+ (1,0) [0|3] ""  IMM
 SG_ M2I_Byrack_ReVeEnable_IMM10_28 : 26|2@1+ (1,0) [0|3] ""  IMM
 SG_ Reserved_28 : 28|4@1+ (1,0) [0|15] ""  IMM
 SG_ M2I_Byrack_IsPostTm_IMM10_28 : 32|8@1+ (0.01,0) [0|2.55] "s"  IMM
 SG_ M2I_Byrack_SysABStTm_IMM10_28 : 40|16@1+ (0.01,0) [0|655.35] "s"  IMM
 SG_ Reserved_28 : 56|8@1+ (1,0) [0|255] ""  IMM

BO_ 2332109485 M2I_Byrack_SUMDATA10__29: 8 MBMU
 SG_ CRC_M2I_Byrack_IMM10_29 : 0|8@1+ (1,0) [0|255] ""  IMM
 SG_ M2I_Byrack_HVS_IMM10_29 : 8|16@1+ (0.1,0) [0|6553.5] "v"  IMM
 SG_ M2I_Byrack_Enable_IMM10_29 : 24|2@1+ (1,0) [0|3] ""  IMM
 SG_ M2I_Byrack_ReVeEnable_IMM10_29 : 26|2@1+ (1,0) [0|3] ""  IMM
 SG_ Reserved_29 : 28|4@1+ (1,0) [0|15] ""  IMM
 SG_ M2I_Byrack_IsPostTm_IMM10_29 : 32|8@1+ (0.01,0) [0|2.55] "s"  IMM
 SG_ M2I_Byrack_SysABStTm_IMM10_29 : 40|16@1+ (0.01,0) [0|655.35] "s"  IMM
 SG_ Reserved_29 : 56|8@1+ (1,0) [0|255] ""  IMM

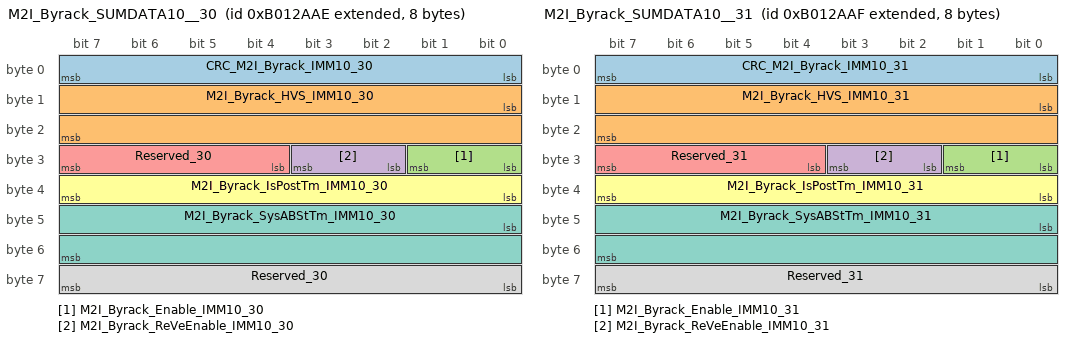
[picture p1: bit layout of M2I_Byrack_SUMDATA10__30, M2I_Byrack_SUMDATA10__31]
BO_ 2332109486 M2I_Byrack_SUMDATA10__30: 8 MBMU
 SG_ CRC_M2I_Byrack_IMM10_30 : 0|8@1+ (1,0) [0|255] ""  IMM
 SG_ M2I_Byrack_HVS_IMM10_30 : 8|16@1+ (0.1,0) [0|6553.5] "v"  IMM
 SG_ M2I_Byrack_Enable_IMM10_30 : 24|2@1+ (1,0) [0|3] ""  IMM
 SG_ M2I_Byrack_ReVeEnable_IMM10_30 : 26|2@1+ (1,0) [0|3] ""  IMM
 SG_ Reserved_30 : 28|4@1+ (1,0) [0|15] ""  IMM
 SG_ M2I_Byrack_IsPostTm_IMM10_30 : 32|8@1+ (0.01,0) [0|2.55] "s"  IMM
 SG_ M2I_Byrack_SysABStTm_IMM10_30 : 40|16@1+ (0.01,0) [0|655.35] "s"  IMM
 SG_ Reserved_30 : 56|8@1+ (1,0) [0|255] ""  IMM

BO_ 2332109487 M2I_Byrack_SUMDATA10__31: 8 MBMU
 SG_ CRC_M2I_Byrack_IMM10_31 : 0|8@1+ (1,0) [0|255] ""  IMM
 SG_ M2I_Byrack_HVS_IMM10_31 : 8|16@1+ (0.1,0) [0|6553.5] "v"  IMM
 SG_ M2I_Byrack_Enable_IMM10_31 : 24|2@1+ (1,0) [0|3] ""  IMM
 SG_ M2I_Byrack_ReVeEnable_IMM10_31 : 26|2@1+ (1,0) [0|3] ""  IMM
 SG_ Reserved_31 : 28|4@1+ (1,0) [0|15] ""  IMM
 SG_ M2I_Byrack_IsPostTm_IMM10_31 : 32|8@1+ (0.01,0) [0|2.55] "s"  IMM
 SG_ M2I_Byrack_SysABStTm_IMM10_31 : 40|16@1+ (0.01,0) [0|655.35] "s"  IMM
 SG_ Reserved_31 : 56|8@1+ (1,0) [0|255] ""  IMM

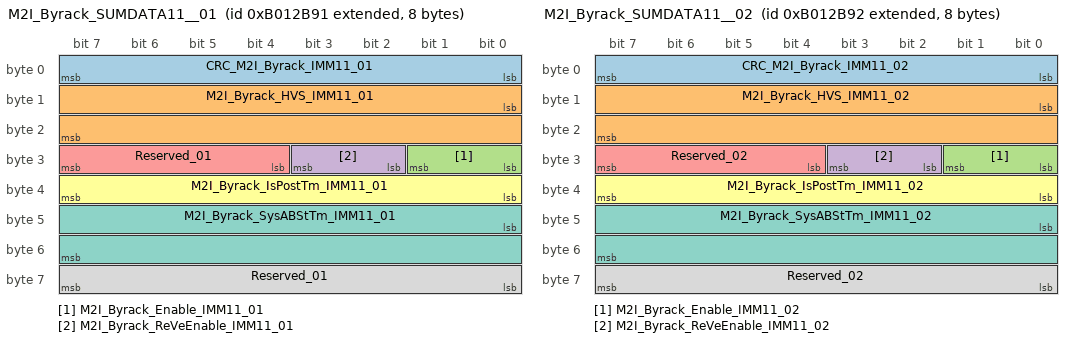
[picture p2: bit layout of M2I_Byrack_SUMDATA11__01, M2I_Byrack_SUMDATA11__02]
BO_ 2332109713 M2I_Byrack_SUMDATA11__01: 8 MBMU
 SG_ CRC_M2I_Byrack_IMM11_01 : 0|8@1+ (1,0) [0|255] ""  IMM
 SG_ M2I_Byrack_HVS_IMM11_01 : 8|16@1+ (0.1,0) [0|6553.5] "v"  IMM
 SG_ M2I_Byrack_Enable_IMM11_01 : 24|2@1+ (1,0) [0|3] ""  IMM
 SG_ M2I_Byrack_ReVeEnable_IMM11_01 : 26|2@1+ (1,0) [0|3] ""  IMM
 SG_ Reserved_01 : 28|4@1+ (1,0) [0|15] ""  IMM
 SG_ M2I_Byrack_IsPostTm_IMM11_01 : 32|8@1+ (0.01,0) [0|2.55] "s"  IMM
 SG_ M2I_Byrack_SysABStTm_IMM11_01 : 40|16@1+ (0.01,0) [0|655.35] "s"  IMM
 SG_ Reserved_01 : 56|8@1+ (1,0) [0|255] ""  IMM

BO_ 2332109714 M2I_Byrack_SUMDATA11__02: 8 MBMU
 SG_ CRC_M2I_Byrack_IMM11_02 : 0|8@1+ (1,0) [0|255] ""  IMM
 SG_ M2I_Byrack_HVS_IMM11_02 : 8|16@1+ (0.1,0) [0|6553.5] "v"  IMM
 SG_ M2I_Byrack_Enable_IMM11_02 : 24|2@1+ (1,0) [0|3] ""  IMM
 SG_ M2I_Byrack_ReVeEnable_IMM11_02 : 26|2@1+ (1,0) [0|3] ""  IMM
 SG_ Reserved_02 : 28|4@1+ (1,0) [0|15] ""  IMM
 SG_ M2I_Byrack_IsPostTm_IMM11_02 : 32|8@1+ (0.01,0) [0|2.55] "s"  IMM
 SG_ M2I_Byrack_SysABStTm_IMM11_02 : 40|16@1+ (0.01,0) [0|655.35] "s"  IMM
 SG_ Reserved_02 : 56|8@1+ (1,0) [0|255] ""  IMM

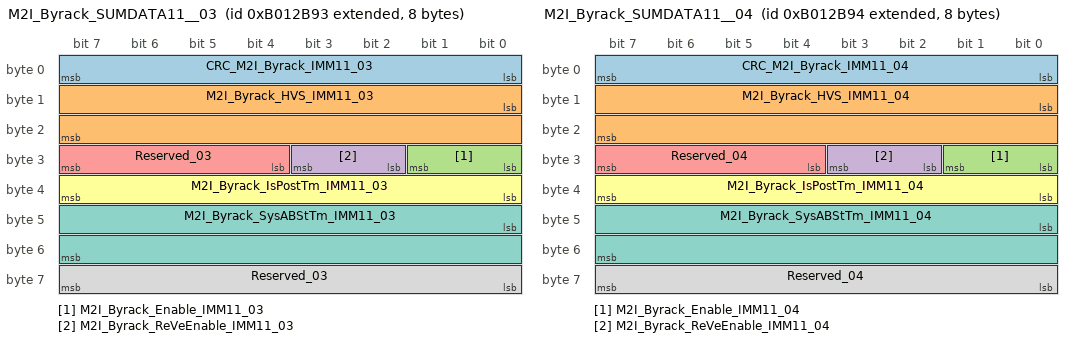
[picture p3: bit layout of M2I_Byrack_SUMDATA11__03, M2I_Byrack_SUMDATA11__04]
BO_ 2332109715 M2I_Byrack_SUMDATA11__03: 8 MBMU
 SG_ CRC_M2I_Byrack_IMM11_03 : 0|8@1+ (1,0) [0|255] ""  IMM
 SG_ M2I_Byrack_HVS_IMM11_03 : 8|16@1+ (0.1,0) [0|6553.5] "v"  IMM
 SG_ M2I_Byrack_Enable_IMM11_03 : 24|2@1+ (1,0) [0|3] ""  IMM
 SG_ M2I_Byrack_ReVeEnable_IMM11_03 : 26|2@1+ (1,0) [0|3] ""  IMM
 SG_ Reserved_03 : 28|4@1+ (1,0) [0|15] ""  IMM
 SG_ M2I_Byrack_IsPostTm_IMM11_03 : 32|8@1+ (0.01,0) [0|2.55] "s"  IMM
 SG_ M2I_Byrack_SysABStTm_IMM11_03 : 40|16@1+ (0.01,0) [0|655.35] "s"  IMM
 SG_ Reserved_03 : 56|8@1+ (1,0) [0|255] ""  IMM

BO_ 2332109716 M2I_Byrack_SUMDATA11__04: 8 MBMU
 SG_ CRC_M2I_Byrack_IMM11_04 : 0|8@1+ (1,0) [0|255] ""  IMM
 SG_ M2I_Byrack_HVS_IMM11_04 : 8|16@1+ (0.1,0) [0|6553.5] "v"  IMM
 SG_ M2I_Byrack_Enable_IMM11_04 : 24|2@1+ (1,0) [0|3] ""  IMM
 SG_ M2I_Byrack_ReVeEnable_IMM11_04 : 26|2@1+ (1,0) [0|3] ""  IMM
 SG_ Reserved_04 : 28|4@1+ (1,0) [0|15] ""  IMM
 SG_ M2I_Byrack_IsPostTm_IMM11_04 : 32|8@1+ (0.01,0) [0|2.55] "s"  IMM
 SG_ M2I_Byrack_SysABStTm_IMM11_04 : 40|16@1+ (0.01,0) [0|655.35] "s"  IMM
 SG_ Reserved_04 : 56|8@1+ (1,0) [0|255] ""  IMM

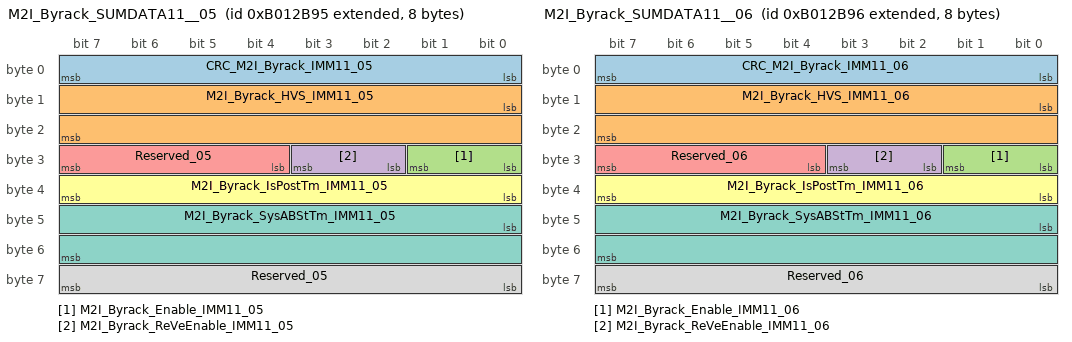
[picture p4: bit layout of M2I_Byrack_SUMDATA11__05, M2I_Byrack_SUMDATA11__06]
BO_ 2332109717 M2I_Byrack_SUMDATA11__05: 8 MBMU
 SG_ CRC_M2I_Byrack_IMM11_05 : 0|8@1+ (1,0) [0|255] ""  IMM
 SG_ M2I_Byrack_HVS_IMM11_05 : 8|16@1+ (0.1,0) [0|6553.5] "v"  IMM
 SG_ M2I_Byrack_Enable_IMM11_05 : 24|2@1+ (1,0) [0|3] ""  IMM
 SG_ M2I_Byrack_ReVeEnable_IMM11_05 : 26|2@1+ (1,0) [0|3] ""  IMM
 SG_ Reserved_05 : 28|4@1+ (1,0) [0|15] ""  IMM
 SG_ M2I_Byrack_IsPostTm_IMM11_05 : 32|8@1+ (0.01,0) [0|2.55] "s"  IMM
 SG_ M2I_Byrack_SysABStTm_IMM11_05 : 40|16@1+ (0.01,0) [0|655.35] "s"  IMM
 SG_ Reserved_05 : 56|8@1+ (1,0) [0|255] ""  IMM

BO_ 2332109718 M2I_Byrack_SUMDATA11__06: 8 MBMU
 SG_ CRC_M2I_Byrack_IMM11_06 : 0|8@1+ (1,0) [0|255] ""  IMM
 SG_ M2I_Byrack_HVS_IMM11_06 : 8|16@1+ (0.1,0) [0|6553.5] "v"  IMM
 SG_ M2I_Byrack_Enable_IMM11_06 : 24|2@1+ (1,0) [0|3] ""  IMM
 SG_ M2I_Byrack_ReVeEnable_IMM11_06 : 26|2@1+ (1,0) [0|3] ""  IMM
 SG_ Reserved_06 : 28|4@1+ (1,0) [0|15] ""  IMM
 SG_ M2I_Byrack_IsPostTm_IMM11_06 : 32|8@1+ (0.01,0) [0|2.55] "s"  IMM
 SG_ M2I_Byrack_SysABStTm_IMM11_06 : 40|16@1+ (0.01,0) [0|655.35] "s"  IMM
 SG_ Reserved_06 : 56|8@1+ (1,0) [0|255] ""  IMM

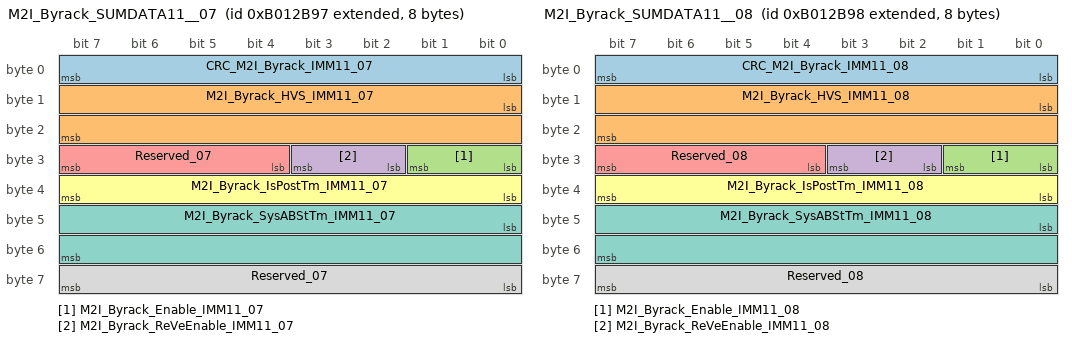
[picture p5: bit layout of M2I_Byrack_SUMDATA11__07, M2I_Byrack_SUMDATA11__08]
BO_ 2332109719 M2I_Byrack_SUMDATA11__07: 8 MBMU
 SG_ CRC_M2I_Byrack_IMM11_07 : 0|8@1+ (1,0) [0|255] ""  IMM
 SG_ M2I_Byrack_HVS_IMM11_07 : 8|16@1+ (0.1,0) [0|6553.5] "v"  IMM
 SG_ M2I_Byrack_Enable_IMM11_07 : 24|2@1+ (1,0) [0|3] ""  IMM
 SG_ M2I_Byrack_ReVeEnable_IMM11_07 : 26|2@1+ (1,0) [0|3] ""  IMM
 SG_ Reserved_07 : 28|4@1+ (1,0) [0|15] ""  IMM
 SG_ M2I_Byrack_IsPostTm_IMM11_07 : 32|8@1+ (0.01,0) [0|2.55] "s"  IMM
 SG_ M2I_Byrack_SysABStTm_IMM11_07 : 40|16@1+ (0.01,0) [0|655.35] "s"  IMM
 SG_ Reserved_07 : 56|8@1+ (1,0) [0|255] ""  IMM

BO_ 2332109720 M2I_Byrack_SUMDATA11__08: 8 MBMU
 SG_ CRC_M2I_Byrack_IMM11_08 : 0|8@1+ (1,0) [0|255] ""  IMM
 SG_ M2I_Byrack_HVS_IMM11_08 : 8|16@1+ (0.1,0) [0|6553.5] "v"  IMM
 SG_ M2I_Byrack_Enable_IMM11_08 : 24|2@1+ (1,0) [0|3] ""  IMM
 SG_ M2I_Byrack_ReVeEnable_IMM11_08 : 26|2@1+ (1,0) [0|3] ""  IMM
 SG_ Reserved_08 : 28|4@1+ (1,0) [0|15] ""  IMM
 SG_ M2I_Byrack_IsPostTm_IMM11_08 : 32|8@1+ (0.01,0) [0|2.55] "s"  IMM
 SG_ M2I_Byrack_SysABStTm_IMM11_08 : 40|16@1+ (0.01,0) [0|655.35] "s"  IMM
 SG_ Reserved_08 : 56|8@1+ (1,0) [0|255] ""  IMM

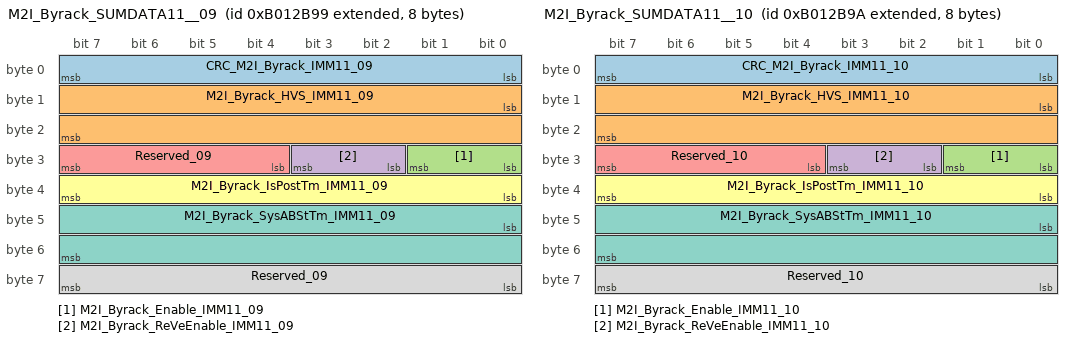
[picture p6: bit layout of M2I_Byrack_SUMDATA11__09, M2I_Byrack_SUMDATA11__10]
BO_ 2332109721 M2I_Byrack_SUMDATA11__09: 8 MBMU
 SG_ CRC_M2I_Byrack_IMM11_09 : 0|8@1+ (1,0) [0|255] ""  IMM
 SG_ M2I_Byrack_HVS_IMM11_09 : 8|16@1+ (0.1,0) [0|6553.5] "v"  IMM
 SG_ M2I_Byrack_Enable_IMM11_09 : 24|2@1+ (1,0) [0|3] ""  IMM
 SG_ M2I_Byrack_ReVeEnable_IMM11_09 : 26|2@1+ (1,0) [0|3] ""  IMM
 SG_ Reserved_09 : 28|4@1+ (1,0) [0|15] ""  IMM
 SG_ M2I_Byrack_IsPostTm_IMM11_09 : 32|8@1+ (0.01,0) [0|2.55] "s"  IMM
 SG_ M2I_Byrack_SysABStTm_IMM11_09 : 40|16@1+ (0.01,0) [0|655.35] "s"  IMM
 SG_ Reserved_09 : 56|8@1+ (1,0) [0|255] ""  IMM

BO_ 2332109722 M2I_Byrack_SUMDATA11__10: 8 MBMU
 SG_ CRC_M2I_Byrack_IMM11_10 : 0|8@1+ (1,0) [0|255] ""  IMM
 SG_ M2I_Byrack_HVS_IMM11_10 : 8|16@1+ (0.1,0) [0|6553.5] "v"  IMM
 SG_ M2I_Byrack_Enable_IMM11_10 : 24|2@1+ (1,0) [0|3] ""  IMM
 SG_ M2I_Byrack_ReVeEnable_IMM11_10 : 26|2@1+ (1,0) [0|3] ""  IMM
 SG_ Reserved_10 : 28|4@1+ (1,0) [0|15] ""  IMM
 SG_ M2I_Byrack_IsPostTm_IMM11_10 : 32|8@1+ (0.01,0) [0|2.55] "s"  IMM
 SG_ M2I_Byrack_SysABStTm_IMM11_10 : 40|16@1+ (0.01,0) [0|655.35] "s"  IMM
 SG_ Reserved_10 : 56|8@1+ (1,0) [0|255] ""  IMM

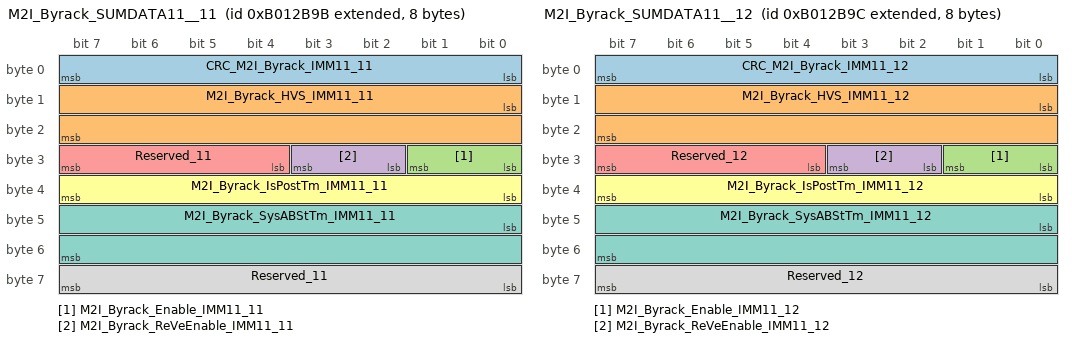
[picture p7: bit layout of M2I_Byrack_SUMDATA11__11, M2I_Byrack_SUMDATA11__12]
BO_ 2332109723 M2I_Byrack_SUMDATA11__11: 8 MBMU
 SG_ CRC_M2I_Byrack_IMM11_11 : 0|8@1+ (1,0) [0|255] ""  IMM
 SG_ M2I_Byrack_HVS_IMM11_11 : 8|16@1+ (0.1,0) [0|6553.5] "v"  IMM
 SG_ M2I_Byrack_Enable_IMM11_11 : 24|2@1+ (1,0) [0|3] ""  IMM
 SG_ M2I_Byrack_ReVeEnable_IMM11_11 : 26|2@1+ (1,0) [0|3] ""  IMM
 SG_ Reserved_11 : 28|4@1+ (1,0) [0|15] ""  IMM
 SG_ M2I_Byrack_IsPostTm_IMM11_11 : 32|8@1+ (0.01,0) [0|2.55] "s"  IMM
 SG_ M2I_Byrack_SysABStTm_IMM11_11 : 40|16@1+ (0.01,0) [0|655.35] "s"  IMM
 SG_ Reserved_11 : 56|8@1+ (1,0) [0|255] ""  IMM

BO_ 2332109724 M2I_Byrack_SUMDATA11__12: 8 MBMU
 SG_ CRC_M2I_Byrack_IMM11_12 : 0|8@1+ (1,0) [0|255] ""  IMM
 SG_ M2I_Byrack_HVS_IMM11_12 : 8|16@1+ (0.1,0) [0|6553.5] "v"  IMM
 SG_ M2I_Byrack_Enable_IMM11_12 : 24|2@1+ (1,0) [0|3] ""  IMM
 SG_ M2I_Byrack_ReVeEnable_IMM11_12 : 26|2@1+ (1,0) [0|3] ""  IMM
 SG_ Reserved_12 : 28|4@1+ (1,0) [0|15] ""  IMM
 SG_ M2I_Byrack_IsPostTm_IMM11_12 : 32|8@1+ (0.01,0) [0|2.55] "s"  IMM
 SG_ M2I_Byrack_SysABStTm_IMM11_12 : 40|16@1+ (0.01,0) [0|655.35] "s"  IMM
 SG_ Reserved_12 : 56|8@1+ (1,0) [0|255] ""  IMM

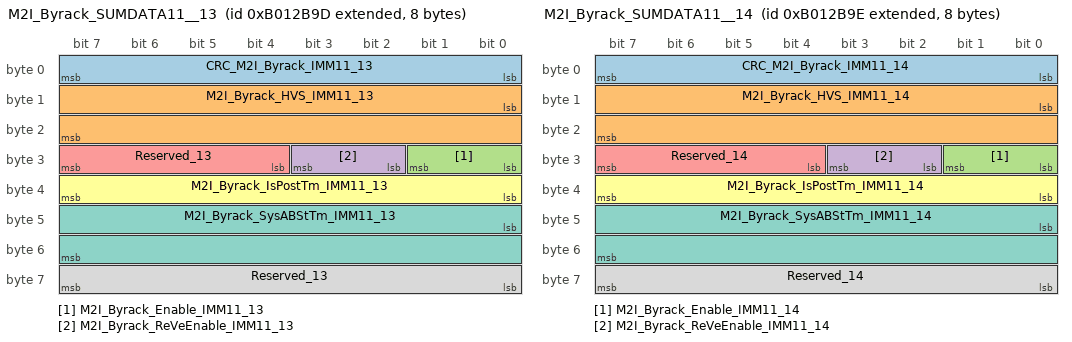
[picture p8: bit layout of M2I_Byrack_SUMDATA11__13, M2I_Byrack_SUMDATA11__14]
BO_ 2332109725 M2I_Byrack_SUMDATA11__13: 8 MBMU
 SG_ CRC_M2I_Byrack_IMM11_13 : 0|8@1+ (1,0) [0|255] ""  IMM
 SG_ M2I_Byrack_HVS_IMM11_13 : 8|16@1+ (0.1,0) [0|6553.5] "v"  IMM
 SG_ M2I_Byrack_Enable_IMM11_13 : 24|2@1+ (1,0) [0|3] ""  IMM
 SG_ M2I_Byrack_ReVeEnable_IMM11_13 : 26|2@1+ (1,0) [0|3] ""  IMM
 SG_ Reserved_13 : 28|4@1+ (1,0) [0|15] ""  IMM
 SG_ M2I_Byrack_IsPostTm_IMM11_13 : 32|8@1+ (0.01,0) [0|2.55] "s"  IMM
 SG_ M2I_Byrack_SysABStTm_IMM11_13 : 40|16@1+ (0.01,0) [0|655.35] "s"  IMM
 SG_ Reserved_13 : 56|8@1+ (1,0) [0|255] ""  IMM

BO_ 2332109726 M2I_Byrack_SUMDATA11__14: 8 MBMU
 SG_ CRC_M2I_Byrack_IMM11_14 : 0|8@1+ (1,0) [0|255] ""  IMM
 SG_ M2I_Byrack_HVS_IMM11_14 : 8|16@1+ (0.1,0) [0|6553.5] "v"  IMM
 SG_ M2I_Byrack_Enable_IMM11_14 : 24|2@1+ (1,0) [0|3] ""  IMM
 SG_ M2I_Byrack_ReVeEnable_IMM11_14 : 26|2@1+ (1,0) [0|3] ""  IMM
 SG_ Reserved_14 : 28|4@1+ (1,0) [0|15] ""  IMM
 SG_ M2I_Byrack_IsPostTm_IMM11_14 : 32|8@1+ (0.01,0) [0|2.55] "s"  IMM
 SG_ M2I_Byrack_SysABStTm_IMM11_14 : 40|16@1+ (0.01,0) [0|655.35] "s"  IMM
 SG_ Reserved_14 : 56|8@1+ (1,0) [0|255] ""  IMM

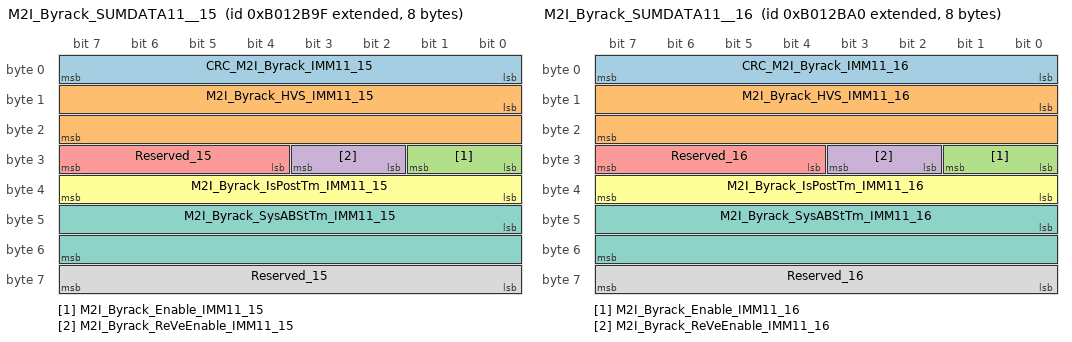
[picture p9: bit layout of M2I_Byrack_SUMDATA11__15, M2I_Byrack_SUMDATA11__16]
BO_ 2332109727 M2I_Byrack_SUMDATA11__15: 8 MBMU
 SG_ CRC_M2I_Byrack_IMM11_15 : 0|8@1+ (1,0) [0|255] ""  IMM
 SG_ M2I_Byrack_HVS_IMM11_15 : 8|16@1+ (0.1,0) [0|6553.5] "v"  IMM
 SG_ M2I_Byrack_Enable_IMM11_15 : 24|2@1+ (1,0) [0|3] ""  IMM
 SG_ M2I_Byrack_ReVeEnable_IMM11_15 : 26|2@1+ (1,0) [0|3] ""  IMM
 SG_ Reserved_15 : 28|4@1+ (1,0) [0|15] ""  IMM
 SG_ M2I_Byrack_IsPostTm_IMM11_15 : 32|8@1+ (0.01,0) [0|2.55] "s"  IMM
 SG_ M2I_Byrack_SysABStTm_IMM11_15 : 40|16@1+ (0.01,0) [0|655.35] "s"  IMM
 SG_ Reserved_15 : 56|8@1+ (1,0) [0|255] ""  IMM

BO_ 2332109728 M2I_Byrack_SUMDATA11__16: 8 MBMU
 SG_ CRC_M2I_Byrack_IMM11_16 : 0|8@1+ (1,0) [0|255] ""  IMM
 SG_ M2I_Byrack_HVS_IMM11_16 : 8|16@1+ (0.1,0) [0|6553.5] "v"  IMM
 SG_ M2I_Byrack_Enable_IMM11_16 : 24|2@1+ (1,0) [0|3] ""  IMM
 SG_ M2I_Byrack_ReVeEnable_IMM11_16 : 26|2@1+ (1,0) [0|3] ""  IMM
 SG_ Reserved_16 : 28|4@1+ (1,0) [0|15] ""  IMM
 SG_ M2I_Byrack_IsPostTm_IMM11_16 : 32|8@1+ (0.01,0) [0|2.55] "s"  IMM
 SG_ M2I_Byrack_SysABStTm_IMM11_16 : 40|16@1+ (0.01,0) [0|655.35] "s"  IMM
 SG_ Reserved_16 : 56|8@1+ (1,0) [0|255] ""  IMM

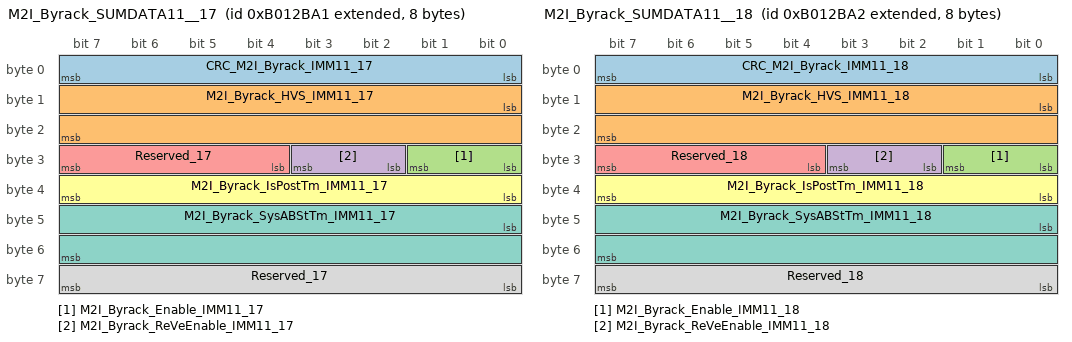
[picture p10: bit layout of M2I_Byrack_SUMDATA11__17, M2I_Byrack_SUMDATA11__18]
BO_ 2332109729 M2I_Byrack_SUMDATA11__17: 8 MBMU
 SG_ CRC_M2I_Byrack_IMM11_17 : 0|8@1+ (1,0) [0|255] ""  IMM
 SG_ M2I_Byrack_HVS_IMM11_17 : 8|16@1+ (0.1,0) [0|6553.5] "v"  IMM
 SG_ M2I_Byrack_Enable_IMM11_17 : 24|2@1+ (1,0) [0|3] ""  IMM
 SG_ M2I_Byrack_ReVeEnable_IMM11_17 : 26|2@1+ (1,0) [0|3] ""  IMM
 SG_ Reserved_17 : 28|4@1+ (1,0) [0|15] ""  IMM
 SG_ M2I_Byrack_IsPostTm_IMM11_17 : 32|8@1+ (0.01,0) [0|2.55] "s"  IMM
 SG_ M2I_Byrack_SysABStTm_IMM11_17 : 40|16@1+ (0.01,0) [0|655.35] "s"  IMM
 SG_ Reserved_17 : 56|8@1+ (1,0) [0|255] ""  IMM

BO_ 2332109730 M2I_Byrack_SUMDATA11__18: 8 MBMU
 SG_ CRC_M2I_Byrack_IMM11_18 : 0|8@1+ (1,0) [0|255] ""  IMM
 SG_ M2I_Byrack_HVS_IMM11_18 : 8|16@1+ (0.1,0) [0|6553.5] "v"  IMM
 SG_ M2I_Byrack_Enable_IMM11_18 : 24|2@1+ (1,0) [0|3] ""  IMM
 SG_ M2I_Byrack_ReVeEnable_IMM11_18 : 26|2@1+ (1,0) [0|3] ""  IMM
 SG_ Reserved_18 : 28|4@1+ (1,0) [0|15] ""  IMM
 SG_ M2I_Byrack_IsPostTm_IMM11_18 : 32|8@1+ (0.01,0) [0|2.55] "s"  IMM
 SG_ M2I_Byrack_SysABStTm_IMM11_18 : 40|16@1+ (0.01,0) [0|655.35] "s"  IMM
 SG_ Reserved_18 : 56|8@1+ (1,0) [0|255] ""  IMM

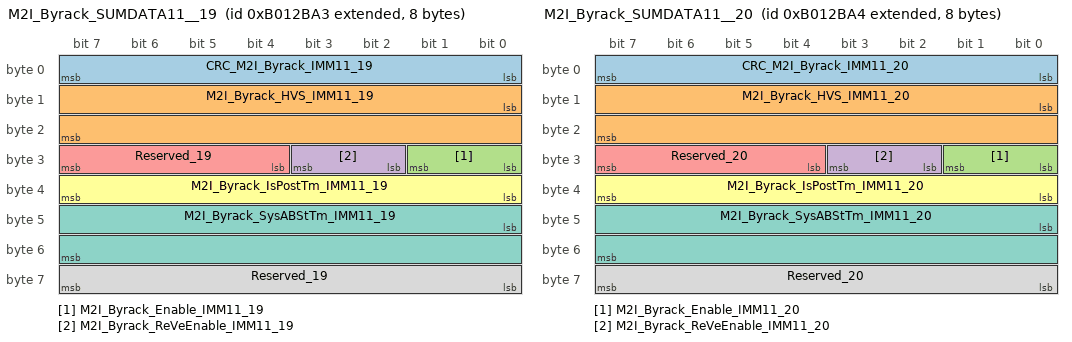
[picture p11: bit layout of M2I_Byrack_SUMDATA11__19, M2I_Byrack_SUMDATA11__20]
BO_ 2332109731 M2I_Byrack_SUMDATA11__19: 8 MBMU
 SG_ CRC_M2I_Byrack_IMM11_19 : 0|8@1+ (1,0) [0|255] ""  IMM
 SG_ M2I_Byrack_HVS_IMM11_19 : 8|16@1+ (0.1,0) [0|6553.5] "v"  IMM
 SG_ M2I_Byrack_Enable_IMM11_19 : 24|2@1+ (1,0) [0|3] ""  IMM
 SG_ M2I_Byrack_ReVeEnable_IMM11_19 : 26|2@1+ (1,0) [0|3] ""  IMM
 SG_ Reserved_19 : 28|4@1+ (1,0) [0|15] ""  IMM
 SG_ M2I_Byrack_IsPostTm_IMM11_19 : 32|8@1+ (0.01,0) [0|2.55] "s"  IMM
 SG_ M2I_Byrack_SysABStTm_IMM11_19 : 40|16@1+ (0.01,0) [0|655.35] "s"  IMM
 SG_ Reserved_19 : 56|8@1+ (1,0) [0|255] ""  IMM

BO_ 2332109732 M2I_Byrack_SUMDATA11__20: 8 MBMU
 SG_ CRC_M2I_Byrack_IMM11_20 : 0|8@1+ (1,0) [0|255] ""  IMM
 SG_ M2I_Byrack_HVS_IMM11_20 : 8|16@1+ (0.1,0) [0|6553.5] "v"  IMM
 SG_ M2I_Byrack_Enable_IMM11_20 : 24|2@1+ (1,0) [0|3] ""  IMM
 SG_ M2I_Byrack_ReVeEnable_IMM11_20 : 26|2@1+ (1,0) [0|3] ""  IMM
 SG_ Reserved_20 : 28|4@1+ (1,0) [0|15] ""  IMM
 SG_ M2I_Byrack_IsPostTm_IMM11_20 : 32|8@1+ (0.01,0) [0|2.55] "s"  IMM
 SG_ M2I_Byrack_SysABStTm_IMM11_20 : 40|16@1+ (0.01,0) [0|655.35] "s"  IMM
 SG_ Reserved_20 : 56|8@1+ (1,0) [0|255] ""  IMM

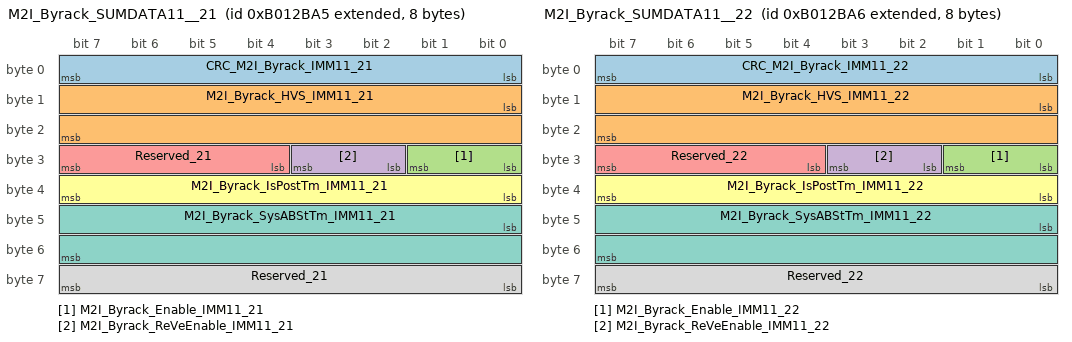
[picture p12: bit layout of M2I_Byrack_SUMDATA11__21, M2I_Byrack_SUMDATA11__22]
BO_ 2332109733 M2I_Byrack_SUMDATA11__21: 8 MBMU
 SG_ CRC_M2I_Byrack_IMM11_21 : 0|8@1+ (1,0) [0|255] ""  IMM
 SG_ M2I_Byrack_HVS_IMM11_21 : 8|16@1+ (0.1,0) [0|6553.5] "v"  IMM
 SG_ M2I_Byrack_Enable_IMM11_21 : 24|2@1+ (1,0) [0|3] ""  IMM
 SG_ M2I_Byrack_ReVeEnable_IMM11_21 : 26|2@1+ (1,0) [0|3] ""  IMM
 SG_ Reserved_21 : 28|4@1+ (1,0) [0|15] ""  IMM
 SG_ M2I_Byrack_IsPostTm_IMM11_21 : 32|8@1+ (0.01,0) [0|2.55] "s"  IMM
 SG_ M2I_Byrack_SysABStTm_IMM11_21 : 40|16@1+ (0.01,0) [0|655.35] "s"  IMM
 SG_ Reserved_21 : 56|8@1+ (1,0) [0|255] ""  IMM

BO_ 2332109734 M2I_Byrack_SUMDATA11__22: 8 MBMU
 SG_ CRC_M2I_Byrack_IMM11_22 : 0|8@1+ (1,0) [0|255] ""  IMM
 SG_ M2I_Byrack_HVS_IMM11_22 : 8|16@1+ (0.1,0) [0|6553.5] "v"  IMM
 SG_ M2I_Byrack_Enable_IMM11_22 : 24|2@1+ (1,0) [0|3] ""  IMM
 SG_ M2I_Byrack_ReVeEnable_IMM11_22 : 26|2@1+ (1,0) [0|3] ""  IMM
 SG_ Reserved_22 : 28|4@1+ (1,0) [0|15] ""  IMM
 SG_ M2I_Byrack_IsPostTm_IMM11_22 : 32|8@1+ (0.01,0) [0|2.55] "s"  IMM
 SG_ M2I_Byrack_SysABStTm_IMM11_22 : 40|16@1+ (0.01,0) [0|655.35] "s"  IMM
 SG_ Reserved_22 : 56|8@1+ (1,0) [0|255] ""  IMM

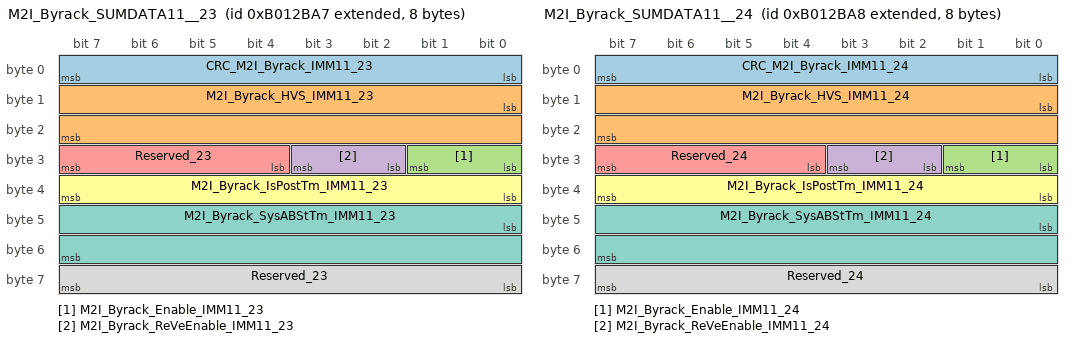
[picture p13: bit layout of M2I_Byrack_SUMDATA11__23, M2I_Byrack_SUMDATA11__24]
BO_ 2332109735 M2I_Byrack_SUMDATA11__23: 8 MBMU
 SG_ CRC_M2I_Byrack_IMM11_23 : 0|8@1+ (1,0) [0|255] ""  IMM
 SG_ M2I_Byrack_HVS_IMM11_23 : 8|16@1+ (0.1,0) [0|6553.5] "v"  IMM
 SG_ M2I_Byrack_Enable_IMM11_23 : 24|2@1+ (1,0) [0|3] ""  IMM
 SG_ M2I_Byrack_ReVeEnable_IMM11_23 : 26|2@1+ (1,0) [0|3] ""  IMM
 SG_ Reserved_23 : 28|4@1+ (1,0) [0|15] ""  IMM
 SG_ M2I_Byrack_IsPostTm_IMM11_23 : 32|8@1+ (0.01,0) [0|2.55] "s"  IMM
 SG_ M2I_Byrack_SysABStTm_IMM11_23 : 40|16@1+ (0.01,0) [0|655.35] "s"  IMM
 SG_ Reserved_23 : 56|8@1+ (1,0) [0|255] ""  IMM

BO_ 2332109736 M2I_Byrack_SUMDATA11__24: 8 MBMU
 SG_ CRC_M2I_Byrack_IMM11_24 : 0|8@1+ (1,0) [0|255] ""  IMM
 SG_ M2I_Byrack_HVS_IMM11_24 : 8|16@1+ (0.1,0) [0|6553.5] "v"  IMM
 SG_ M2I_Byrack_Enable_IMM11_24 : 24|2@1+ (1,0) [0|3] ""  IMM
 SG_ M2I_Byrack_ReVeEnable_IMM11_24 : 26|2@1+ (1,0) [0|3] ""  IMM
 SG_ Reserved_24 : 28|4@1+ (1,0) [0|15] ""  IMM
 SG_ M2I_Byrack_IsPostTm_IMM11_24 : 32|8@1+ (0.01,0) [0|2.55] "s"  IMM
 SG_ M2I_Byrack_SysABStTm_IMM11_24 : 40|16@1+ (0.01,0) [0|655.35] "s"  IMM
 SG_ Reserved_24 : 56|8@1+ (1,0) [0|255] ""  IMM

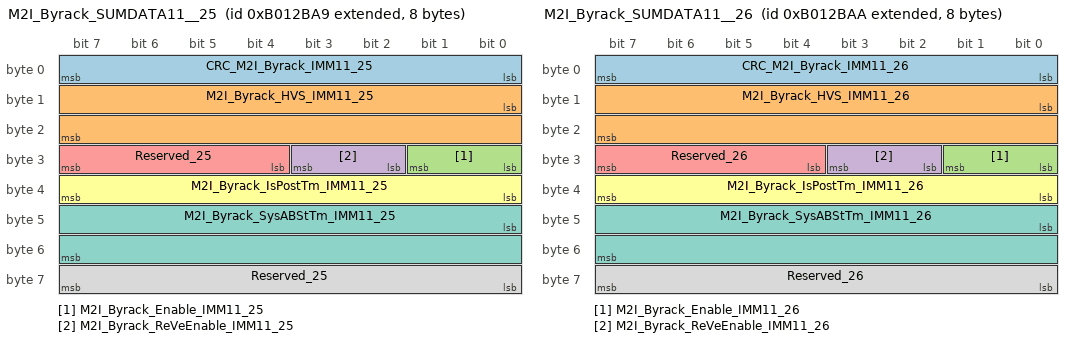
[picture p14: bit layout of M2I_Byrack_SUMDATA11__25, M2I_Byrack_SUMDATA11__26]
BO_ 2332109737 M2I_Byrack_SUMDATA11__25: 8 MBMU
 SG_ CRC_M2I_Byrack_IMM11_25 : 0|8@1+ (1,0) [0|255] ""  IMM
 SG_ M2I_Byrack_HVS_IMM11_25 : 8|16@1+ (0.1,0) [0|6553.5] "v"  IMM
 SG_ M2I_Byrack_Enable_IMM11_25 : 24|2@1+ (1,0) [0|3] ""  IMM
 SG_ M2I_Byrack_ReVeEnable_IMM11_25 : 26|2@1+ (1,0) [0|3] ""  IMM
 SG_ Reserved_25 : 28|4@1+ (1,0) [0|15] ""  IMM
 SG_ M2I_Byrack_IsPostTm_IMM11_25 : 32|8@1+ (0.01,0) [0|2.55] "s"  IMM
 SG_ M2I_Byrack_SysABStTm_IMM11_25 : 40|16@1+ (0.01,0) [0|655.35] "s"  IMM
 SG_ Reserved_25 : 56|8@1+ (1,0) [0|255] ""  IMM

BO_ 2332109738 M2I_Byrack_SUMDATA11__26: 8 MBMU
 SG_ CRC_M2I_Byrack_IMM11_26 : 0|8@1+ (1,0) [0|255] ""  IMM
 SG_ M2I_Byrack_HVS_IMM11_26 : 8|16@1+ (0.1,0) [0|6553.5] "v"  IMM
 SG_ M2I_Byrack_Enable_IMM11_26 : 24|2@1+ (1,0) [0|3] ""  IMM
 SG_ M2I_Byrack_ReVeEnable_IMM11_26 : 26|2@1+ (1,0) [0|3] ""  IMM
 SG_ Reserved_26 : 28|4@1+ (1,0) [0|15] ""  IMM
 SG_ M2I_Byrack_IsPostTm_IMM11_26 : 32|8@1+ (0.01,0) [0|2.55] "s"  IMM
 SG_ M2I_Byrack_SysABStTm_IMM11_26 : 40|16@1+ (0.01,0) [0|655.35] "s"  IMM
 SG_ Reserved_26 : 56|8@1+ (1,0) [0|255] ""  IMM

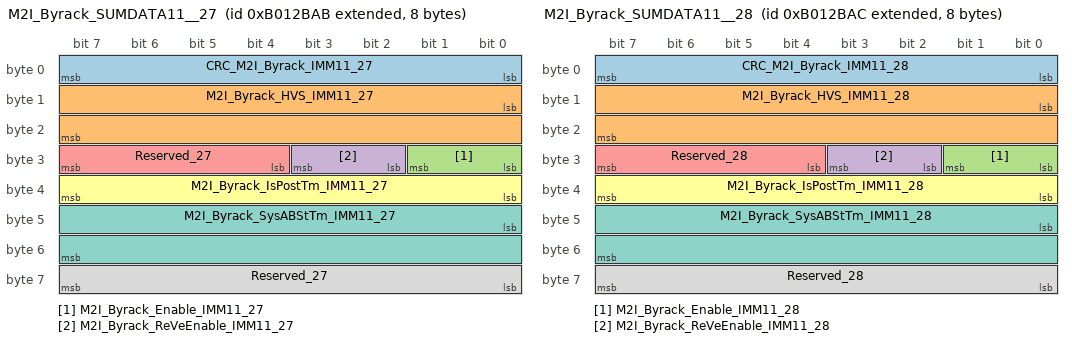
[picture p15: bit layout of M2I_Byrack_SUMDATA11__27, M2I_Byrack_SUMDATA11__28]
BO_ 2332109739 M2I_Byrack_SUMDATA11__27: 8 MBMU
 SG_ CRC_M2I_Byrack_IMM11_27 : 0|8@1+ (1,0) [0|255] ""  IMM
 SG_ M2I_Byrack_HVS_IMM11_27 : 8|16@1+ (0.1,0) [0|6553.5] "v"  IMM
 SG_ M2I_Byrack_Enable_IMM11_27 : 24|2@1+ (1,0) [0|3] ""  IMM
 SG_ M2I_Byrack_ReVeEnable_IMM11_27 : 26|2@1+ (1,0) [0|3] ""  IMM
 SG_ Reserved_27 : 28|4@1+ (1,0) [0|15] ""  IMM
 SG_ M2I_Byrack_IsPostTm_IMM11_27 : 32|8@1+ (0.01,0) [0|2.55] "s"  IMM
 SG_ M2I_Byrack_SysABStTm_IMM11_27 : 40|16@1+ (0.01,0) [0|655.35] "s"  IMM
 SG_ Reserved_27 : 56|8@1+ (1,0) [0|255] ""  IMM

BO_ 2332109740 M2I_Byrack_SUMDATA11__28: 8 MBMU
 SG_ CRC_M2I_Byrack_IMM11_28 : 0|8@1+ (1,0) [0|255] ""  IMM
 SG_ M2I_Byrack_HVS_IMM11_28 : 8|16@1+ (0.1,0) [0|6553.5] "v"  IMM
 SG_ M2I_Byrack_Enable_IMM11_28 : 24|2@1+ (1,0) [0|3] ""  IMM
 SG_ M2I_Byrack_ReVeEnable_IMM11_28 : 26|2@1+ (1,0) [0|3] ""  IMM
 SG_ Reserved_28 : 28|4@1+ (1,0) [0|15] ""  IMM
 SG_ M2I_Byrack_IsPostTm_IMM11_28 : 32|8@1+ (0.01,0) [0|2.55] "s"  IMM
 SG_ M2I_Byrack_SysABStTm_IMM11_28 : 40|16@1+ (0.01,0) [0|655.35] "s"  IMM
 SG_ Reserved_28 : 56|8@1+ (1,0) [0|255] ""  IMM

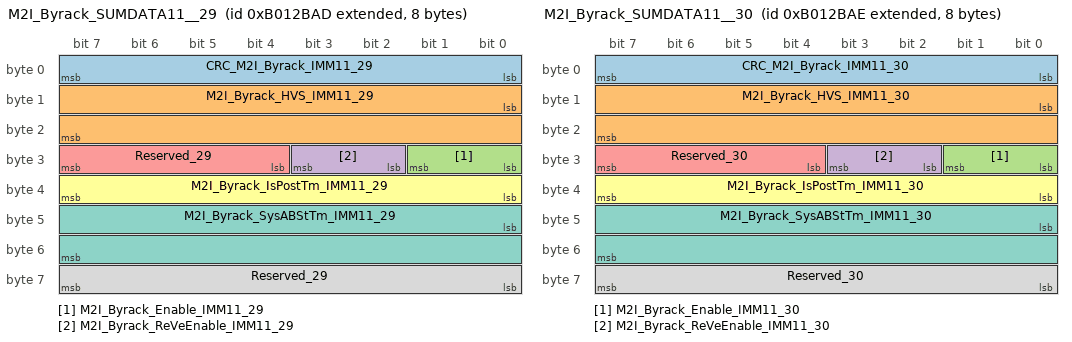
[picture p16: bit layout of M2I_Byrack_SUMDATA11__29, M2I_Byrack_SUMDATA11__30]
BO_ 2332109741 M2I_Byrack_SUMDATA11__29: 8 MBMU
 SG_ CRC_M2I_Byrack_IMM11_29 : 0|8@1+ (1,0) [0|255] ""  IMM
 SG_ M2I_Byrack_HVS_IMM11_29 : 8|16@1+ (0.1,0) [0|6553.5] "v"  IMM
 SG_ M2I_Byrack_Enable_IMM11_29 : 24|2@1+ (1,0) [0|3] ""  IMM
 SG_ M2I_Byrack_ReVeEnable_IMM11_29 : 26|2@1+ (1,0) [0|3] ""  IMM
 SG_ Reserved_29 : 28|4@1+ (1,0) [0|15] ""  IMM
 SG_ M2I_Byrack_IsPostTm_IMM11_29 : 32|8@1+ (0.01,0) [0|2.55] "s"  IMM
 SG_ M2I_Byrack_SysABStTm_IMM11_29 : 40|16@1+ (0.01,0) [0|655.35] "s"  IMM
 SG_ Reserved_29 : 56|8@1+ (1,0) [0|255] ""  IMM

BO_ 2332109742 M2I_Byrack_SUMDATA11__30: 8 MBMU
 SG_ CRC_M2I_Byrack_IMM11_30 : 0|8@1+ (1,0) [0|255] ""  IMM
 SG_ M2I_Byrack_HVS_IMM11_30 : 8|16@1+ (0.1,0) [0|6553.5] "v"  IMM
 SG_ M2I_Byrack_Enable_IMM11_30 : 24|2@1+ (1,0) [0|3] ""  IMM
 SG_ M2I_Byrack_ReVeEnable_IMM11_30 : 26|2@1+ (1,0) [0|3] ""  IMM
 SG_ Reserved_30 : 28|4@1+ (1,0) [0|15] ""  IMM
 SG_ M2I_Byrack_IsPostTm_IMM11_30 : 32|8@1+ (0.01,0) [0|2.55] "s"  IMM
 SG_ M2I_Byrack_SysABStTm_IMM11_30 : 40|16@1+ (0.01,0) [0|655.35] "s"  IMM
 SG_ Reserved_30 : 56|8@1+ (1,0) [0|255] ""  IMM

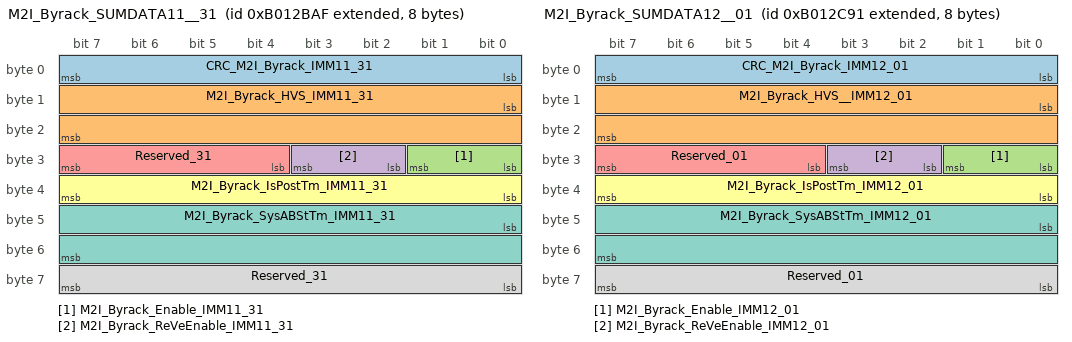
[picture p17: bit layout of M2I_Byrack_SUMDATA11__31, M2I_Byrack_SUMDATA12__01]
BO_ 2332109743 M2I_Byrack_SUMDATA11__31: 8 MBMU
 SG_ CRC_M2I_Byrack_IMM11_31 : 0|8@1+ (1,0) [0|255] ""  IMM
 SG_ M2I_Byrack_HVS_IMM11_31 : 8|16@1+ (0.1,0) [0|6553.5] "v"  IMM
 SG_ M2I_Byrack_Enable_IMM11_31 : 24|2@1+ (1,0) [0|3] ""  IMM
 SG_ M2I_Byrack_ReVeEnable_IMM11_31 : 26|2@1+ (1,0) [0|3] ""  IMM
 SG_ Reserved_31 : 28|4@1+ (1,0) [0|15] ""  IMM
 SG_ M2I_Byrack_IsPostTm_IMM11_31 : 32|8@1+ (0.01,0) [0|2.55] "s"  IMM
 SG_ M2I_Byrack_SysABStTm_IMM11_31 : 40|16@1+ (0.01,0) [0|655.35] "s"  IMM
 SG_ Reserved_31 : 56|8@1+ (1,0) [0|255] ""  IMM

BO_ 2332109969 M2I_Byrack_SUMDATA12__01: 8 MBMU
 SG_ CRC_M2I_Byrack_IMM12_01 : 0|8@1+ (1,0) [0|255] ""  IMM
 SG_ M2I_Byrack_HVS__IMM12_01 : 8|16@1+ (0.1,0) [0|6553.5] "v"  IMM
 SG_ M2I_Byrack_Enable_IMM12_01 : 24|2@1+ (1,0) [0|3] ""  IMM
 SG_ M2I_Byrack_ReVeEnable_IMM12_01 : 26|2@1+ (1,0) [0|3] ""  IMM
 SG_ Reserved_01 : 28|4@1+ (1,0) [0|15] ""  IMM
 SG_ M2I_Byrack_IsPostTm_IMM12_01 : 32|8@1+ (0.01,0) [0|2.55] "s"  IMM
 SG_ M2I_Byrack_SysABStTm_IMM12_01 : 40|16@1+ (0.01,0) [0|655.35] "s"  IMM
 SG_ Reserved_01 : 56|8@1+ (1,0) [0|255] ""  IMM

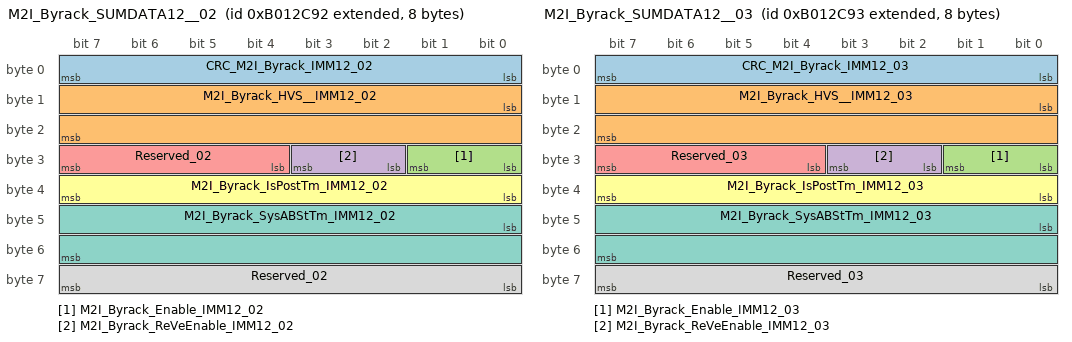
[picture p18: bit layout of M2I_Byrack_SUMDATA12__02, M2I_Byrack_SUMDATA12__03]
BO_ 2332109970 M2I_Byrack_SUMDATA12__02: 8 MBMU
 SG_ CRC_M2I_Byrack_IMM12_02 : 0|8@1+ (1,0) [0|255] ""  IMM
 SG_ M2I_Byrack_HVS__IMM12_02 : 8|16@1+ (0.1,0) [0|6553.5] "v"  IMM
 SG_ M2I_Byrack_Enable_IMM12_02 : 24|2@1+ (1,0) [0|3] ""  IMM
 SG_ M2I_Byrack_ReVeEnable_IMM12_02 : 26|2@1+ (1,0) [0|3] ""  IMM
 SG_ Reserved_02 : 28|4@1+ (1,0) [0|15] ""  IMM
 SG_ M2I_Byrack_IsPostTm_IMM12_02 : 32|8@1+ (0.01,0) [0|2.55] "s"  IMM
 SG_ M2I_Byrack_SysABStTm_IMM12_02 : 40|16@1+ (0.01,0) [0|655.35] "s"  IMM
 SG_ Reserved_02 : 56|8@1+ (1,0) [0|255] ""  IMM

BO_ 2332109971 M2I_Byrack_SUMDATA12__03: 8 MBMU
 SG_ CRC_M2I_Byrack_IMM12_03 : 0|8@1+ (1,0) [0|255] ""  IMM
 SG_ M2I_Byrack_HVS__IMM12_03 : 8|16@1+ (0.1,0) [0|6553.5] "v"  IMM
 SG_ M2I_Byrack_Enable_IMM12_03 : 24|2@1+ (1,0) [0|3] ""  IMM
 SG_ M2I_Byrack_ReVeEnable_IMM12_03 : 26|2@1+ (1,0) [0|3] ""  IMM
 SG_ Reserved_03 : 28|4@1+ (1,0) [0|15] ""  IMM
 SG_ M2I_Byrack_IsPostTm_IMM12_03 : 32|8@1+ (0.01,0) [0|2.55] "s"  IMM
 SG_ M2I_Byrack_SysABStTm_IMM12_03 : 40|16@1+ (0.01,0) [0|655.35] "s"  IMM
 SG_ Reserved_03 : 56|8@1+ (1,0) [0|255] ""  IMM

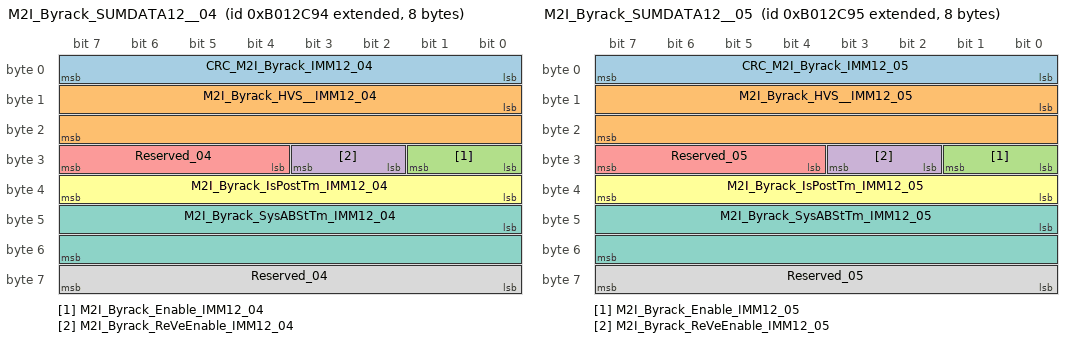
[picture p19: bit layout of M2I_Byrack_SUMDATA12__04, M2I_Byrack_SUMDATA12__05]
BO_ 2332109972 M2I_Byrack_SUMDATA12__04: 8 MBMU
 SG_ CRC_M2I_Byrack_IMM12_04 : 0|8@1+ (1,0) [0|255] ""  IMM
 SG_ M2I_Byrack_HVS__IMM12_04 : 8|16@1+ (0.1,0) [0|6553.5] "v"  IMM
 SG_ M2I_Byrack_Enable_IMM12_04 : 24|2@1+ (1,0) [0|3] ""  IMM
 SG_ M2I_Byrack_ReVeEnable_IMM12_04 : 26|2@1+ (1,0) [0|3] ""  IMM
 SG_ Reserved_04 : 28|4@1+ (1,0) [0|15] ""  IMM
 SG_ M2I_Byrack_IsPostTm_IMM12_04 : 32|8@1+ (0.01,0) [0|2.55] "s"  IMM
 SG_ M2I_Byrack_SysABStTm_IMM12_04 : 40|16@1+ (0.01,0) [0|655.35] "s"  IMM
 SG_ Reserved_04 : 56|8@1+ (1,0) [0|255] ""  IMM

BO_ 2332109973 M2I_Byrack_SUMDATA12__05: 8 MBMU
 SG_ CRC_M2I_Byrack_IMM12_05 : 0|8@1+ (1,0) [0|255] ""  IMM
 SG_ M2I_Byrack_HVS__IMM12_05 : 8|16@1+ (0.1,0) [0|6553.5] "v"  IMM
 SG_ M2I_Byrack_Enable_IMM12_05 : 24|2@1+ (1,0) [0|3] ""  IMM
 SG_ M2I_Byrack_ReVeEnable_IMM12_05 : 26|2@1+ (1,0) [0|3] ""  IMM
 SG_ Reserved_05 : 28|4@1+ (1,0) [0|15] ""  IMM
 SG_ M2I_Byrack_IsPostTm_IMM12_05 : 32|8@1+ (0.01,0) [0|2.55] "s"  IMM
 SG_ M2I_Byrack_SysABStTm_IMM12_05 : 40|16@1+ (0.01,0) [0|655.35] "s"  IMM
 SG_ Reserved_05 : 56|8@1+ (1,0) [0|255] ""  IMM

BO_ 2332109974 M2I_Byrack_SUMDATA12__06: 8 MBMU
 SG_ CRC_M2I_Byrack_IMM12_06 : 0|8@1+ (1,0) [0|255] ""  IMM
 SG_ M2I_Byrack_HVS__IMM12_06 : 8|16@1+ (0.1,0) [0|6553.5] "v"  IMM
 SG_ M2I_Byrack_Enable_IMM12_06 : 24|2@1+ (1,0) [0|3] ""  IMM
 SG_ M2I_Byrack_ReVeEnable_IMM12_06 : 26|2@1+ (1,0) [0|3] ""  IMM
 SG_ Reserved_06 : 28|4@1+ (1,0) [0|15] ""  IMM
 SG_ M2I_Byrack_IsPostTm_IMM12_06 : 32|8@1+ (0.01,0) [0|2.55] "s"  IMM
 SG_ M2I_Byrack_SysABStTm_IMM12_06 : 40|16@1+ (0.01,0) [0|655.35] "s"  IMM
 SG_ Reserved_06 : 56|8@1+ (1,0) [0|255] ""  IMM

BO_ 2332109975 M2I_Byrack_SUMDATA12__07: 8 MBMU
 SG_ CRC_M2I_Byrack_IMM12_07 : 0|8@1+ (1,0) [0|255] ""  IMM
 SG_ M2I_Byrack_HVS__IMM12_07 : 8|16@1+ (0.1,0) [0|6553.5] "v"  IMM
 SG_ M2I_Byrack_Enable_IMM12_07 : 24|2@1+ (1,0) [0|3] ""  IMM
 SG_ M2I_Byrack_ReVeEnable_IMM12_07 : 26|2@1+ (1,0) [0|3] ""  IMM
 SG_ Reserved_07 : 28|4@1+ (1,0) [0|15] ""  IMM
 SG_ M2I_Byrack_IsPostTm_IMM12_07 : 32|8@1+ (0.01,0) [0|2.55] "s"  IMM
 SG_ M2I_Byrack_SysABStTm_IMM12_07 : 40|16@1+ (0.01,0) [0|655.35] "s"  IMM
 SG_ Reserved_07 : 56|8@1+ (1,0) [0|255] ""  IMM

BO_ 2332109976 M2I_Byrack_SUMDATA12__08: 8 MBMU
 SG_ CRC_M2I_Byrack_IMM12_08 : 0|8@1+ (1,0) [0|255] ""  IMM
 SG_ M2I_Byrack_HVS__IMM12_08 : 8|16@1+ (0.1,0) [0|6553.5] "v"  IMM
 SG_ M2I_Byrack_Enable_IMM12_08 : 24|2@1+ (1,0) [0|3] ""  IMM
 SG_ M2I_Byrack_ReVeEnable_IMM12_08 : 26|2@1+ (1,0) [0|3] ""  IMM
 SG_ Reserved_08 : 28|4@1+ (1,0) [0|15] ""  IMM
 SG_ M2I_Byrack_IsPostTm_IMM12_08 : 32|8@1+ (0.01,0) [0|2.55] "s"  IMM
 SG_ M2I_Byrack_SysABStTm_IMM12_08 : 40|16@1+ (0.01,0) [0|655.35] "s"  IMM
 SG_ Reserved_08 : 56|8@1+ (1,0) [0|255] ""  IMM

BO_ 2332109977 M2I_Byrack_SUMDATA12__09: 8 MBMU
 SG_ CRC_M2I_Byrack_IMM12_09 : 0|8@1+ (1,0) [0|255] ""  IMM
 SG_ M2I_Byrack_HVS__IMM12_09 : 8|16@1+ (0.1,0) [0|6553.5] "v"  IMM
 SG_ M2I_Byrack_Enable_IMM12_09 : 24|2@1+ (1,0) [0|3] ""  IMM
 SG_ M2I_Byrack_ReVeEnable_IMM12_09 : 26|2@1+ (1,0) [0|3] ""  IMM
 SG_ Reserved_09 : 28|4@1+ (1,0) [0|15] ""  IMM
 SG_ M2I_Byrack_IsPostTm_IMM12_09 : 32|8@1+ (0.01,0) [0|2.55] "s"  IMM
 SG_ M2I_Byrack_SysABStTm_IMM12_09 : 40|16@1+ (0.01,0) [0|655.35] "s"  IMM
 SG_ Reserved_09 : 56|8@1+ (1,0) [0|255] ""  IMM

BO_ 2332109978 M2I_Byrack_SUMDATA12__10: 8 MBMU
 SG_ CRC_M2I_Byrack_IMM12_10 : 0|8@1+ (1,0) [0|255] ""  IMM
 SG_ M2I_Byrack_HVS__IMM12_10 : 8|16@1+ (0.1,0) [0|6553.5] "v"  IMM
 SG_ M2I_Byrack_Enable_IMM12_10 : 24|2@1+ (1,0) [0|3] ""  IMM
 SG_ M2I_Byrack_ReVeEnable_IMM12_10 : 26|2@1+ (1,0) [0|3] ""  IMM
 SG_ Reserved_10 : 28|4@1+ (1,0) [0|15] ""  IMM
 SG_ M2I_Byrack_IsPostTm_IMM12_10 : 32|8@1+ (0.01,0) [0|2.55] "s"  IMM
 SG_ M2I_Byrack_SysABStTm_IMM12_10 : 40|16@1+ (0.01,0) [0|655.35] "s"  IMM
 SG_ Reserved_10 : 56|8@1+ (1,0) [0|255] ""  IMM

BO_ 2332109979 M2I_Byrack_SUMDATA12__11: 8 MBMU
 SG_ CRC_M2I_Byrack_IMM12_11 : 0|8@1+ (1,0) [0|255] ""  IMM
 SG_ M2I_Byrack_HVS__IMM12_11 : 8|16@1+ (0.1,0) [0|6553.5] "v"  IMM
 SG_ M2I_Byrack_Enable_IMM12_11 : 24|2@1+ (1,0) [0|3] ""  IMM
 SG_ M2I_Byrack_ReVeEnable_IMM12_11 : 26|2@1+ (1,0) [0|3] ""  IMM
 SG_ Reserved_11 : 28|4@1+ (1,0) [0|15] ""  IMM
 SG_ M2I_Byrack_IsPostTm_IMM12_11 : 32|8@1+ (0.01,0) [0|2.55] "s"  IMM
 SG_ M2I_Byrack_SysABStTm_IMM12_11 : 40|16@1+ (0.01,0) [0|655.35] "s"  IMM
 SG_ Reserved_11 : 56|8@1+ (1,0) [0|255] ""  IMM

BO_ 2332109980 M2I_Byrack_SUMDATA12__12: 8 MBMU
 SG_ CRC_M2I_Byrack_IMM12_12 : 0|8@1+ (1,0) [0|255] ""  IMM
 SG_ M2I_Byrack_HVS__IMM12_12 : 8|16@1+ (0.1,0) [0|6553.5] "v"  IMM
 SG_ M2I_Byrack_Enable_IMM12_12 : 24|2@1+ (1,0) [0|3] ""  IMM
 SG_ M2I_Byrack_ReVeEnable_IMM12_12 : 26|2@1+ (1,0) [0|3] ""  IMM
 SG_ Reserved_12 : 28|4@1+ (1,0) [0|15] ""  IMM
 SG_ M2I_Byrack_IsPostTm_IMM12_12 : 32|8@1+ (0.01,0) [0|2.55] "s"  IMM
 SG_ M2I_Byrack_SysABStTm_IMM12_12 : 40|16@1+ (0.01,0) [0|655.35] "s"  IMM
 SG_ Reserved_12 : 56|8@1+ (1,0) [0|255] ""  IMM

BO_ 2332109981 M2I_Byrack_SUMDATA12__13: 8 MBMU
 SG_ CRC_M2I_Byrack_IMM12_13 : 0|8@1+ (1,0) [0|255] ""  IMM
 SG_ M2I_Byrack_HVS__IMM12_13 : 8|16@1+ (0.1,0) [0|6553.5] "v"  IMM
 SG_ M2I_Byrack_Enable_IMM12_13 : 24|2@1+ (1,0) [0|3] ""  IMM
 SG_ M2I_Byrack_ReVeEnable_IMM12_13 : 26|2@1+ (1,0) [0|3] ""  IMM
 SG_ Reserved_13 : 28|4@1+ (1,0) [0|15] ""  IMM
 SG_ M2I_Byrack_IsPostTm_IMM12_13 : 32|8@1+ (0.01,0) [0|2.55] "s"  IMM
 SG_ M2I_Byrack_SysABStTm_IMM12_13 : 40|16@1+ (0.01,0) [0|655.35] "s"  IMM
 SG_ Reserved_13 : 56|8@1+ (1,0) [0|255] ""  IMM

BO_ 2332109982 M2I_Byrack_SUMDATA12__14: 8 MBMU
 SG_ CRC_M2I_Byrack_IMM12_14 : 0|8@1+ (1,0) [0|255] ""  IMM
 SG_ M2I_Byrack_HVS__IMM12_14 : 8|16@1+ (0.1,0) [0|6553.5] "v"  IMM
 SG_ M2I_Byrack_Enable_IMM12_14 : 24|2@1+ (1,0) [0|3] ""  IMM
 SG_ M2I_Byrack_ReVeEnable_IMM12_14 : 26|2@1+ (1,0) [0|3] ""  IMM
 SG_ Reserved_14 : 28|4@1+ (1,0) [0|15] ""  IMM
 SG_ M2I_Byrack_IsPostTm_IMM12_14 : 32|8@1+ (0.01,0) [0|2.55] "s"  IMM
 SG_ M2I_Byrack_SysABStTm_IMM12_14 : 40|16@1+ (0.01,0) [0|655.35] "s"  IMM
 SG_ Reserved_14 : 56|8@1+ (1,0) [0|255] ""  IMM

BO_ 2332109983 M2I_Byrack_SUMDATA12__15: 8 MBMU
 SG_ CRC_M2I_Byrack_IMM12_15 : 0|8@1+ (1,0) [0|255] ""  IMM
 SG_ M2I_Byrack_HVS__IMM12_15 : 8|16@1+ (0.1,0) [0|6553.5] "v"  IMM
 SG_ M2I_Byrack_Enable_IMM12_15 : 24|2@1+ (1,0) [0|3] ""  IMM
 SG_ M2I_Byrack_ReVeEnable_IMM12_15 : 26|2@1+ (1,0) [0|3] ""  IMM
 SG_ Reserved_15 : 28|4@1+ (1,0) [0|15] ""  IMM
 SG_ M2I_Byrack_IsPostTm_IMM12_15 : 32|8@1+ (0.01,0) [0|2.55] "s"  IMM
 SG_ M2I_Byrack_SysABStTm_IMM12_15 : 40|16@1+ (0.01,0) [0|655.35] "s"  IMM
 SG_ Reserved_15 : 56|8@1+ (1,0) [0|255] ""  IMM

BO_ 2332109984 M2I_Byrack_SUMDATA12__16: 8 MBMU
 SG_ CRC_M2I_Byrack_IMM12_16 : 0|8@1+ (1,0) [0|255] ""  IMM
 SG_ M2I_Byrack_HVS__IMM12_16 : 8|16@1+ (0.1,0) [0|6553.5] "v"  IMM
 SG_ M2I_Byrack_Enable_IMM12_16 : 24|2@1+ (1,0) [0|3] ""  IMM
 SG_ M2I_Byrack_ReVeEnable_IMM12_16 : 26|2@1+ (1,0) [0|3] ""  IMM
 SG_ Reserved_16 : 28|4@1+ (1,0) [0|15] ""  IMM
 SG_ M2I_Byrack_IsPostTm_IMM12_16 : 32|8@1+ (0.01,0) [0|2.55] "s"  IMM
 SG_ M2I_Byrack_SysABStTm_IMM12_16 : 40|16@1+ (0.01,0) [0|655.35] "s"  IMM
 SG_ Reserved_16 : 56|8@1+ (1,0) [0|255] ""  IMM

BO_ 2332109985 M2I_Byrack_SUMDATA12__17: 8 MBMU
 SG_ CRC_M2I_Byrack_IMM12_17 : 0|8@1+ (1,0) [0|255] ""  IMM
 SG_ M2I_Byrack_HVS__IMM12_17 : 8|16@1+ (0.1,0) [0|6553.5] "v"  IMM
 SG_ M2I_Byrack_Enable_IMM12_17 : 24|2@1+ (1,0) [0|3] ""  IMM
 SG_ M2I_Byrack_ReVeEnable_IMM12_17 : 26|2@1+ (1,0) [0|3] ""  IMM
 SG_ Reserved_17 : 28|4@1+ (1,0) [0|15] ""  IMM
 SG_ M2I_Byrack_IsPostTm_IMM12_17 : 32|8@1+ (0.01,0) [0|2.55] "s"  IMM
 SG_ M2I_Byrack_SysABStTm_IMM12_17 : 40|16@1+ (0.01,0) [0|655.35] "s"  IMM
 SG_ Reserved_17 : 56|8@1+ (1,0) [0|255] ""  IMM

BO_ 2332109986 M2I_Byrack_SUMDATA12__18: 8 MBMU
 SG_ CRC_M2I_Byrack_IMM12_18 : 0|8@1+ (1,0) [0|255] ""  IMM
 SG_ M2I_Byrack_HVS__IMM12_18 : 8|16@1+ (0.1,0) [0|6553.5] "v"  IMM
 SG_ M2I_Byrack_Enable_IMM12_18 : 24|2@1+ (1,0) [0|3] ""  IMM
 SG_ M2I_Byrack_ReVeEnable_IMM12_18 : 26|2@1+ (1,0) [0|3] ""  IMM
 SG_ Reserved_18 : 28|4@1+ (1,0) [0|15] ""  IMM
 SG_ M2I_Byrack_IsPostTm_IMM12_18 : 32|8@1+ (0.01,0) [0|2.55] "s"  IMM
 SG_ M2I_Byrack_SysABStTm_IMM12_18 : 40|16@1+ (0.01,0) [0|655.35] "s"  IMM
 SG_ Reserved_18 : 56|8@1+ (1,0) [0|255] ""  IMM

BO_ 2332109987 M2I_Byrack_SUMDATA12__19: 8 MBMU
 SG_ CRC_M2I_Byrack_IMM12_19 : 0|8@1+ (1,0) [0|255] ""  IMM
 SG_ M2I_Byrack_HVS__IMM12_19 : 8|16@1+ (0.1,0) [0|6553.5] "v"  IMM
 SG_ M2I_Byrack_Enable_IMM12_19 : 24|2@1+ (1,0) [0|3] ""  IMM
 SG_ M2I_Byrack_ReVeEnable_IMM12_19 : 26|2@1+ (1,0) [0|3] ""  IMM
 SG_ Reserved_19 : 28|4@1+ (1,0) [0|15] ""  IMM
 SG_ M2I_Byrack_IsPostTm_IMM12_19 : 32|8@1+ (0.01,0) [0|2.55] "s"  IMM
 SG_ M2I_Byrack_SysABStTm_IMM12_19 : 40|16@1+ (0.01,0) [0|655.35] "s"  IMM
 SG_ Reserved_19 : 56|8@1+ (1,0) [0|255] ""  IMM

BO_ 2332109988 M2I_Byrack_SUMDATA12__20: 8 MBMU
 SG_ CRC_M2I_Byrack_IMM12_20 : 0|8@1+ (1,0) [0|255] ""  IMM
 SG_ M2I_Byrack_HVS__IMM12_20 : 8|16@1+ (0.1,0) [0|6553.5] "v"  IMM
 SG_ M2I_Byrack_Enable_IMM12_20 : 24|2@1+ (1,0) [0|3] ""  IMM
 SG_ M2I_Byrack_ReVeEnable_IMM12_20 : 26|2@1+ (1,0) [0|3] ""  IMM
 SG_ Reserved_20 : 28|4@1+ (1,0) [0|15] ""  IMM
 SG_ M2I_Byrack_IsPostTm_IMM12_20 : 32|8@1+ (0.01,0) [0|2.55] "s"  IMM
 SG_ M2I_Byrack_SysABStTm_IMM12_20 : 40|16@1+ (0.01,0) [0|655.35] "s"  IMM
 SG_ Reserved_20 : 56|8@1+ (1,0) [0|255] ""  IMM

BO_ 2332109989 M2I_Byrack_SUMDATA12__21: 8 MBMU
 SG_ CRC_M2I_Byrack_IMM12_21 : 0|8@1+ (1,0) [0|255] ""  IMM
 SG_ M2I_Byrack_HVS__IMM12_21 : 8|16@1+ (0.1,0) [0|6553.5] "v"  IMM
 SG_ M2I_Byrack_Enable_IMM12_21 : 24|2@1+ (1,0) [0|3] ""  IMM
 SG_ M2I_Byrack_ReVeEnable_IMM12_21 : 26|2@1+ (1,0) [0|3] ""  IMM
 SG_ Reserved_21 : 28|4@1+ (1,0) [0|15] ""  IMM
 SG_ M2I_Byrack_IsPostTm_IMM12_21 : 32|8@1+ (0.01,0) [0|2.55] "s"  IMM
 SG_ M2I_Byrack_SysABStTm_IMM12_21 : 40|16@1+ (0.01,0) [0|655.35] "s"  IMM
 SG_ Reserved_21 : 56|8@1+ (1,0) [0|255] ""  IMM

BO_ 2332109990 M2I_Byrack_SUMDATA12__22: 8 MBMU
 SG_ CRC_M2I_Byrack_IMM12_22 : 0|8@1+ (1,0) [0|255] ""  IMM
 SG_ M2I_Byrack_HVS__IMM12_22 : 8|16@1+ (0.1,0) [0|6553.5] "v"  IMM
 SG_ M2I_Byrack_Enable_IMM12_22 : 24|2@1+ (1,0) [0|3] ""  IMM
 SG_ M2I_Byrack_ReVeEnable_IMM12_22 : 26|2@1+ (1,0) [0|3] ""  IMM
 SG_ Reserved_22 : 28|4@1+ (1,0) [0|15] ""  IMM
 SG_ M2I_Byrack_IsPostTm_IMM12_22 : 32|8@1+ (0.01,0) [0|2.55] "s"  IMM
 SG_ M2I_Byrack_SysABStTm_IMM12_22 : 40|16@1+ (0.01,0) [0|655.35] "s"  IMM
 SG_ Reserved_22 : 56|8@1+ (1,0) [0|255] ""  IMM

BO_ 2332109991 M2I_Byrack_SUMDATA12__23: 8 MBMU
 SG_ CRC_M2I_Byrack_IMM12_23 : 0|8@1+ (1,0) [0|255] ""  IMM
 SG_ M2I_Byrack_HVS__IMM12_23 : 8|16@1+ (0.1,0) [0|6553.5] "v"  IMM
 SG_ M2I_Byrack_Enable_IMM12_23 : 24|2@1+ (1,0) [0|3] ""  IMM
 SG_ M2I_Byrack_ReVeEnable_IMM12_23 : 26|2@1+ (1,0) [0|3] ""  IMM
 SG_ Reserved_23 : 28|4@1+ (1,0) [0|15] ""  IMM
 SG_ M2I_Byrack_IsPostTm_IMM12_23 : 32|8@1+ (0.01,0) [0|2.55] "s"  IMM
 SG_ M2I_Byrack_SysABStTm_IMM12_23 : 40|16@1+ (0.01,0) [0|655.35] "s"  IMM
 SG_ Reserved_23 : 56|8@1+ (1,0) [0|255] ""  IMM

BO_ 2332109992 M2I_Byrack_SUMDATA12__24: 8 MBMU
 SG_ CRC_M2I_Byrack_IMM12_24 : 0|8@1+ (1,0) [0|255] ""  IMM
 SG_ M2I_Byrack_HVS__IMM12_24 : 8|16@1+ (0.1,0) [0|6553.5] "v"  IMM
 SG_ M2I_Byrack_Enable_IMM12_24 : 24|2@1+ (1,0) [0|3] ""  IMM
 SG_ M2I_Byrack_ReVeEnable_IMM12_24 : 26|2@1+ (1,0) [0|3] ""  IMM
 SG_ Reserved_24 : 28|4@1+ (1,0) [0|15] ""  IMM
 SG_ M2I_Byrack_IsPostTm_IMM12_24 : 32|8@1+ (0.01,0) [0|2.55] "s"  IMM
 SG_ M2I_Byrack_SysABStTm_IMM12_24 : 40|16@1+ (0.01,0) [0|655.35] "s"  IMM
 SG_ Reserved_24 : 56|8@1+ (1,0) [0|255] ""  IMM

BO_ 2332109993 M2I_Byrack_SUMDATA12__25: 8 MBMU
 SG_ CRC_M2I_Byrack_IMM12_25 : 0|8@1+ (1,0) [0|255] ""  IMM
 SG_ M2I_Byrack_HVS__IMM12_25 : 8|16@1+ (0.1,0) [0|6553.5] "v"  IMM
 SG_ M2I_Byrack_Enable_IMM12_25 : 24|2@1+ (1,0) [0|3] ""  IMM
 SG_ M2I_Byrack_ReVeEnable_IMM12_25 : 26|2@1+ (1,0) [0|3] ""  IMM
 SG_ Reserved_25 : 28|4@1+ (1,0) [0|15] ""  IMM
 SG_ M2I_Byrack_IsPostTm_IMM12_25 : 32|8@1+ (0.01,0) [0|2.55] "s"  IMM
 SG_ M2I_Byrack_SysABStTm_IMM12_25 : 40|16@1+ (0.01,0) [0|655.35] "s"  IMM
 SG_ Reserved_25 : 56|8@1+ (1,0) [0|255] ""  IMM

BO_ 2332109994 M2I_Byrack_SUMDATA12__26: 8 MBMU
 SG_ CRC_M2I_Byrack_IMM12_26 : 0|8@1+ (1,0) [0|255] ""  IMM
 SG_ M2I_Byrack_HVS__IMM12_26 : 8|16@1+ (0.1,0) [0|6553.5] "v"  IMM
 SG_ M2I_Byrack_Enable_IMM12_26 : 24|2@1+ (1,0) [0|3] ""  IMM
 SG_ M2I_Byrack_ReVeEnable_IMM12_26 : 26|2@1+ (1,0) [0|3] ""  IMM
 SG_ Reserved_26 : 28|4@1+ (1,0) [0|15] ""  IMM
 SG_ M2I_Byrack_IsPostTm_IMM12_26 : 32|8@1+ (0.01,0) [0|2.55] "s"  IMM
 SG_ M2I_Byrack_SysABStTm_IMM12_26 : 40|16@1+ (0.01,0) [0|655.35] "s"  IMM
 SG_ Reserved_26 : 56|8@1+ (1,0) [0|255] ""  IMM

BO_ 2332109995 M2I_Byrack_SUMDATA12__27: 8 MBMU
 SG_ CRC_M2I_Byrack_IMM12_27 : 0|8@1+ (1,0) [0|255] ""  IMM
 SG_ M2I_Byrack_HVS__IMM12_27 : 8|16@1+ (0.1,0) [0|6553.5] "v"  IMM
 SG_ M2I_Byrack_Enable_IMM12_27 : 24|2@1+ (1,0) [0|3] ""  IMM
 SG_ M2I_Byrack_ReVeEnable_IMM12_27 : 26|2@1+ (1,0) [0|3] ""  IMM
 SG_ Reserved_27 : 28|4@1+ (1,0) [0|15] ""  IMM
 SG_ M2I_Byrack_IsPostTm_IMM12_27 : 32|8@1+ (0.01,0) [0|2.55] "s"  IMM
 SG_ M2I_Byrack_SysABStTm_IMM12_27 : 40|16@1+ (0.01,0) [0|655.35] "s"  IMM
 SG_ Reserved_27 : 56|8@1+ (1,0) [0|255] ""  IMM

BO_ 2332109996 M2I_Byrack_SUMDATA12__28: 8 MBMU
 SG_ CRC_M2I_Byrack_IMM12_28 : 0|8@1+ (1,0) [0|255] ""  IMM
 SG_ M2I_Byrack_HVS__IMM12_28 : 8|16@1+ (0.1,0) [0|6553.5] "v"  IMM
 SG_ M2I_Byrack_Enable_IMM12_28 : 24|2@1+ (1,0) [0|3] ""  IMM
 SG_ M2I_Byrack_ReVeEnable_IMM12_28 : 26|2@1+ (1,0) [0|3] ""  IMM
 SG_ Reserved_28 : 28|4@1+ (1,0) [0|15] ""  IMM
 SG_ M2I_Byrack_IsPostTm_IMM12_28 : 32|8@1+ (0.01,0) [0|2.55] "s"  IMM
 SG_ M2I_Byrack_SysABStTm_IMM12_28 : 40|16@1+ (0.01,0) [0|655.35] "s"  IMM
 SG_ Reserved_28 : 56|8@1+ (1,0) [0|255] ""  IMM

BO_ 2332109997 M2I_Byrack_SUMDATA12__29: 8 MBMU
 SG_ CRC_M2I_Byrack_IMM12_29 : 0|8@1+ (1,0) [0|255] ""  IMM
 SG_ M2I_Byrack_HVS__IMM12_29 : 8|16@1+ (0.1,0) [0|6553.5] "v"  IMM
 SG_ M2I_Byrack_Enable_IMM12_29 : 24|2@1+ (1,0) [0|3] ""  IMM
 SG_ M2I_Byrack_ReVeEnable_IMM12_29 : 26|2@1+ (1,0) [0|3] ""  IMM
 SG_ Reserved_29 : 28|4@1+ (1,0) [0|15] ""  IMM
 SG_ M2I_Byrack_IsPostTm_IMM12_29 : 32|8@1+ (0.01,0) [0|2.55] "s"  IMM
 SG_ M2I_Byrack_SysABStTm_IMM12_29 : 40|16@1+ (0.01,0) [0|655.35] "s"  IMM
 SG_ Reserved_29 : 56|8@1+ (1,0) [0|255] ""  IMM

BO_ 2332109998 M2I_Byrack_SUMDATA12__30: 8 MBMU
 SG_ CRC_M2I_Byrack_IMM12_30 : 0|8@1+ (1,0) [0|255] ""  IMM
 SG_ M2I_Byrack_HVS__IMM12_30 : 8|16@1+ (0.1,0) [0|6553.5] "v"  IMM
 SG_ M2I_Byrack_Enable_IMM12_30 : 24|2@1+ (1,0) [0|3] ""  IMM
 SG_ M2I_Byrack_ReVeEnable_IMM12_30 : 26|2@1+ (1,0) [0|3] ""  IMM
 SG_ Reserved_30 : 28|4@1+ (1,0) [0|15] ""  IMM
 SG_ M2I_Byrack_IsPostTm_IMM12_30 : 32|8@1+ (0.01,0) [0|2.55] "s"  IMM
 SG_ M2I_Byrack_SysABStTm_IMM12_30 : 40|16@1+ (0.01,0) [0|655.35] "s"  IMM
 SG_ Reserved_30 : 56|8@1+ (1,0) [0|255] ""  IMM

BO_ 2332109999 M2I_Byrack_SUMDATA12__31: 8 MBMU
 SG_ CRC_M2I_Byrack_IMM12_31 : 0|8@1+ (1,0) [0|255] ""  IMM
 SG_ M2I_Byrack_HVS__IMM12_31 : 8|16@1+ (0.1,0) [0|6553.5] "v"  IMM
 SG_ M2I_Byrack_Enable_IMM12_31 : 24|2@1+ (1,0) [0|3] ""  IMM
 SG_ M2I_Byrack_ReVeEnable_IMM12_31 : 26|2@1+ (1,0) [0|3] ""  IMM
 SG_ Reserved_31 : 28|4@1+ (1,0) [0|15] ""  IMM
 SG_ M2I_Byrack_IsPostTm_IMM12_31 : 32|8@1+ (0.01,0) [0|2.55] "s"  IMM
 SG_ M2I_Byrack_SysABStTm_IMM12_31 : 40|16@1+ (0.01,0) [0|655.35] "s"  IMM
 SG_ Reserved_31 : 56|8@1+ (1,0) [0|255] ""  IMM

BO_ 2332110225 M2I_Byrack_SUMDATA13__01: 8 MBMU
 SG_ CRC_M2I_Byrack_IMM13_01 : 0|8@1+ (1,0) [0|255] ""  IMM
 SG_ M2I_Byrack_HVS__IMM13_01 : 8|16@1+ (0.1,0) [0|6553.5] "v"  IMM
 SG_ M2I_Byrack_Enable_IMM13_01 : 24|2@1+ (1,0) [0|3] ""  IMM
 SG_ M2I_Byrack_ReVeEnable_IMM13_01 : 26|2@1+ (1,0) [0|3] ""  IMM
 SG_ Reserved_01 : 28|4@1+ (1,0) [0|15] ""  IMM
 SG_ M2I_Byrack_IsPostTm_IMM13_01 : 32|8@1+ (0.01,0) [0|2.55] "s"  IMM
 SG_ M2I_Byrack_SysABStTm_IMM13_01 : 40|16@1+ (0.01,0) [0|655.35] "s"  IMM
 SG_ Reserved_01 : 56|8@1+ (1,0) [0|255] ""  IMM

BO_ 2332110226 M2I_Byrack_SUMDATA13__02: 8 MBMU
 SG_ CRC_M2I_Byrack_IMM13_02 : 0|8@1+ (1,0) [0|255] ""  IMM
 SG_ M2I_Byrack_HVS__IMM13_02 : 8|16@1+ (0.1,0) [0|6553.5] "v"  IMM
 SG_ M2I_Byrack_Enable_IMM13_02 : 24|2@1+ (1,0) [0|3] ""  IMM
 SG_ M2I_Byrack_ReVeEnable_IMM13_02 : 26|2@1+ (1,0) [0|3] ""  IMM
 SG_ Reserved_02 : 28|4@1+ (1,0) [0|15] ""  IMM
 SG_ M2I_Byrack_IsPostTm_IMM13_02 : 32|8@1+ (0.01,0) [0|2.55] "s"  IMM
 SG_ M2I_Byrack_SysABStTm_IMM13_02 : 40|16@1+ (0.01,0) [0|655.35] "s"  IMM
 SG_ Reserved_02 : 56|8@1+ (1,0) [0|255] ""  IMM

BO_ 2332110227 M2I_Byrack_SUMDATA13__03: 8 MBMU
 SG_ CRC_M2I_Byrack_IMM13_03 : 0|8@1+ (1,0) [0|255] ""  IMM
 SG_ M2I_Byrack_HVS__IMM13_03 : 8|16@1+ (0.1,0) [0|6553.5] "v"  IMM
 SG_ M2I_Byrack_Enable_IMM13_03 : 24|2@1+ (1,0) [0|3] ""  IMM
 SG_ M2I_Byrack_ReVeEnable_IMM13_03 : 26|2@1+ (1,0) [0|3] ""  IMM
 SG_ Reserved_03 : 28|4@1+ (1,0) [0|15] ""  IMM
 SG_ M2I_Byrack_IsPostTm_IMM13_03 : 32|8@1+ (0.01,0) [0|2.55] "s"  IMM
 SG_ M2I_Byrack_SysABStTm_IMM13_03 : 40|16@1+ (0.01,0) [0|655.35] "s"  IMM
 SG_ Reserved_03 : 56|8@1+ (1,0) [0|255] ""  IMM

BO_ 2332110228 M2I_Byrack_SUMDATA13__04: 8 MBMU
 SG_ CRC_M2I_Byrack_IMM13_04 : 0|8@1+ (1,0) [0|255] ""  IMM
 SG_ M2I_Byrack_HVS__IMM13_04 : 8|16@1+ (0.1,0) [0|6553.5] "v"  IMM
 SG_ M2I_Byrack_Enable_IMM13_04 : 24|2@1+ (1,0) [0|3] ""  IMM
 SG_ M2I_Byrack_ReVeEnable_IMM13_04 : 26|2@1+ (1,0) [0|3] ""  IMM
 SG_ Reserved_04 : 28|4@1+ (1,0) [0|15] ""  IMM
 SG_ M2I_Byrack_IsPostTm_IMM13_04 : 32|8@1+ (0.01,0) [0|2.55] "s"  IMM
 SG_ M2I_Byrack_SysABStTm_IMM13_04 : 40|16@1+ (0.01,0) [0|655.35] "s"  IMM
 SG_ Reserved_04 : 56|8@1+ (1,0) [0|255] ""  IMM

BO_ 2332110229 M2I_Byrack_SUMDATA13__05: 8 MBMU
 SG_ CRC_M2I_Byrack_IMM13_05 : 0|8@1+ (1,0) [0|255] ""  IMM
 SG_ M2I_Byrack_HVS__IMM13_05 : 8|16@1+ (0.1,0) [0|6553.5] "v"  IMM
 SG_ M2I_Byrack_Enable_IMM13_05 : 24|2@1+ (1,0) [0|3] ""  IMM
 SG_ M2I_Byrack_ReVeEnable_IMM13_05 : 26|2@1+ (1,0) [0|3] ""  IMM
 SG_ Reserved_05 : 28|4@1+ (1,0) [0|15] ""  IMM
 SG_ M2I_Byrack_IsPostTm_IMM13_05 : 32|8@1+ (0.01,0) [0|2.55] "s"  IMM
 SG_ M2I_Byrack_SysABStTm_IMM13_05 : 40|16@1+ (0.01,0) [0|655.35] "s"  IMM
 SG_ Reserved_05 : 56|8@1+ (1,0) [0|255] ""  IMM

BO_ 2332110230 M2I_Byrack_SUMDATA13__06: 8 MBMU
 SG_ CRC_M2I_Byrack_IMM13_06 : 0|8@1+ (1,0) [0|255] ""  IMM
 SG_ M2I_Byrack_HVS__IMM13_06 : 8|16@1+ (0.1,0) [0|6553.5] "v"  IMM
 SG_ M2I_Byrack_Enable_IMM13_06 : 24|2@1+ (1,0) [0|3] ""  IMM
 SG_ M2I_Byrack_ReVeEnable_IMM13_06 : 26|2@1+ (1,0) [0|3] ""  IMM
 SG_ Reserved_06 : 28|4@1+ (1,0) [0|15] ""  IMM
 SG_ M2I_Byrack_IsPostTm_IMM13_06 : 32|8@1+ (0.01,0) [0|2.55] "s"  IMM
 SG_ M2I_Byrack_SysABStTm_IMM13_06 : 40|16@1+ (0.01,0) [0|655.35] "s"  IMM
 SG_ Reserved_06 : 56|8@1+ (1,0) [0|255] ""  IMM

BO_ 2332110231 M2I_Byrack_SUMDATA13__07: 8 MBMU
 SG_ CRC_M2I_Byrack_IMM13_07 : 0|8@1+ (1,0) [0|255] ""  IMM
 SG_ M2I_Byrack_HVS__IMM13_07 : 8|16@1+ (0.1,0) [0|6553.5] "v"  IMM
 SG_ M2I_Byrack_Enable_IMM13_07 : 24|2@1+ (1,0) [0|3] ""  IMM
 SG_ M2I_Byrack_ReVeEnable_IMM13_07 : 26|2@1+ (1,0) [0|3] ""  IMM
 SG_ Reserved_07 : 28|4@1+ (1,0) [0|15] ""  IMM
 SG_ M2I_Byrack_IsPostTm_IMM13_07 : 32|8@1+ (0.01,0) [0|2.55] "s"  IMM
 SG_ M2I_Byrack_SysABStTm_IMM13_07 : 40|16@1+ (0.01,0) [0|655.35] "s"  IMM
 SG_ Reserved_07 : 56|8@1+ (1,0) [0|255] ""  IMM

BO_ 2332110232 M2I_Byrack_SUMDATA13__08: 8 MBMU
 SG_ CRC_M2I_Byrack_IMM13_08 : 0|8@1+ (1,0) [0|255] ""  IMM
 SG_ M2I_Byrack_HVS__IMM13_08 : 8|16@1+ (0.1,0) [0|6553.5] "v"  IMM
 SG_ M2I_Byrack_Enable_IMM13_08 : 24|2@1+ (1,0) [0|3] ""  IMM
 SG_ M2I_Byrack_ReVeEnable_IMM13_08 : 26|2@1+ (1,0) [0|3] ""  IMM
 SG_ Reserved_08 : 28|4@1+ (1,0) [0|15] ""  IMM
 SG_ M2I_Byrack_IsPostTm_IMM13_08 : 32|8@1+ (0.01,0) [0|2.55] "s"  IMM
 SG_ M2I_Byrack_SysABStTm_IMM13_08 : 40|16@1+ (0.01,0) [0|655.35] "s"  IMM
 SG_ Reserved_08 : 56|8@1+ (1,0) [0|255] ""  IMM

BO_ 2332110233 M2I_Byrack_SUMDATA13__09: 8 MBMU
 SG_ CRC_M2I_Byrack_IMM13_09 : 0|8@1+ (1,0) [0|255] ""  IMM
 SG_ M2I_Byrack_HVS__IMM13_09 : 8|16@1+ (0.1,0) [0|6553.5] "v"  IMM
 SG_ M2I_Byrack_Enable_IMM13_09 : 24|2@1+ (1,0) [0|3] ""  IMM
 SG_ M2I_Byrack_ReVeEnable_IMM13_09 : 26|2@1+ (1,0) [0|3] ""  IMM
 SG_ Reserved_09 : 28|4@1+ (1,0) [0|15] ""  IMM
 SG_ M2I_Byrack_IsPostTm_IMM13_09 : 32|8@1+ (0.01,0) [0|2.55] "s"  IMM
 SG_ M2I_Byrack_SysABStTm_IMM13_09 : 40|16@1+ (0.01,0) [0|655.35] "s"  IMM
 SG_ Reserved_09 : 56|8@1+ (1,0) [0|255] ""  IMM

BO_ 2332110234 M2I_Byrack_SUMDATA13__10: 8 MBMU
 SG_ CRC_M2I_Byrack_IMM13_10 : 0|8@1+ (1,0) [0|255] ""  IMM
 SG_ M2I_Byrack_HVS__IMM13_10 : 8|16@1+ (0.1,0) [0|6553.5] "v"  IMM
 SG_ M2I_Byrack_Enable_IMM13_10 : 24|2@1+ (1,0) [0|3] ""  IMM
 SG_ M2I_Byrack_ReVeEnable_IMM13_10 : 26|2@1+ (1,0) [0|3] ""  IMM
 SG_ Reserved_10 : 28|4@1+ (1,0) [0|15] ""  IMM
 SG_ M2I_Byrack_IsPostTm_IMM13_10 : 32|8@1+ (0.01,0) [0|2.55] "s"  IMM
 SG_ M2I_Byrack_SysABStTm_IMM13_10 : 40|16@1+ (0.01,0) [0|655.35] "s"  IMM
 SG_ Reserved_10 : 56|8@1+ (1,0) [0|255] ""  IMM

BO_ 2332110235 M2I_Byrack_SUMDATA13__11: 8 MBMU
 SG_ CRC_M2I_Byrack_IMM13_11 : 0|8@1+ (1,0) [0|255] ""  IMM
 SG_ M2I_Byrack_HVS__IMM13_11 : 8|16@1+ (0.1,0) [0|6553.5] "v"  IMM
 SG_ M2I_Byrack_Enable_IMM13_11 : 24|2@1+ (1,0) [0|3] ""  IMM
 SG_ M2I_Byrack_ReVeEnable_IMM13_11 : 26|2@1+ (1,0) [0|3] ""  IMM
 SG_ Reserved_11 : 28|4@1+ (1,0) [0|15] ""  IMM
 SG_ M2I_Byrack_IsPostTm_IMM13_11 : 32|8@1+ (0.01,0) [0|2.55] "s"  IMM
 SG_ M2I_Byrack_SysABStTm_IMM13_11 : 40|16@1+ (0.01,0) [0|655.35] "s"  IMM
 SG_ Reserved_11 : 56|8@1+ (1,0) [0|255] ""  IMM

BO_ 2332110236 M2I_Byrack_SUMDATA13__12: 8 MBMU
 SG_ CRC_M2I_Byrack_IMM13_12 : 0|8@1+ (1,0) [0|255] ""  IMM
 SG_ M2I_Byrack_HVS__IMM13_12 : 8|16@1+ (0.1,0) [0|6553.5] "v"  IMM
 SG_ M2I_Byrack_Enable_IMM13_12 : 24|2@1+ (1,0) [0|3] ""  IMM
 SG_ M2I_Byrack_ReVeEnable_IMM13_12 : 26|2@1+ (1,0) [0|3] ""  IMM
 SG_ Reserved_12 : 28|4@1+ (1,0) [0|15] ""  IMM
 SG_ M2I_Byrack_IsPostTm_IMM13_12 : 32|8@1+ (0.01,0) [0|2.55] "s"  IMM
 SG_ M2I_Byrack_SysABStTm_IMM13_12 : 40|16@1+ (0.01,0) [0|655.35] "s"  IMM
 SG_ Reserved_12 : 56|8@1+ (1,0) [0|255] ""  IMM

BO_ 2332110237 M2I_Byrack_SUMDATA13__13: 8 MBMU
 SG_ CRC_M2I_Byrack_IMM13_13 : 0|8@1+ (1,0) [0|255] ""  IMM
 SG_ M2I_Byrack_HVS__IMM13_13 : 8|16@1+ (0.1,0) [0|6553.5] "v"  IMM
 SG_ M2I_Byrack_Enable_IMM13_13 : 24|2@1+ (1,0) [0|3] ""  IMM
 SG_ M2I_Byrack_ReVeEnable_IMM13_13 : 26|2@1+ (1,0) [0|3] ""  IMM
 SG_ Reserved_13 : 28|4@1+ (1,0) [0|15] ""  IMM
 SG_ M2I_Byrack_IsPostTm_IMM13_13 : 32|8@1+ (0.01,0) [0|2.55] "s"  IMM
 SG_ M2I_Byrack_SysABStTm_IMM13_13 : 40|16@1+ (0.01,0) [0|655.35] "s"  IMM
 SG_ Reserved_13 : 56|8@1+ (1,0) [0|255] ""  IMM

BO_ 2332110238 M2I_Byrack_SUMDATA13__14: 8 MBMU
 SG_ CRC_M2I_Byrack_IMM13_14 : 0|8@1+ (1,0) [0|255] ""  IMM
 SG_ M2I_Byrack_HVS__IMM13_14 : 8|16@1+ (0.1,0) [0|6553.5] "v"  IMM
 SG_ M2I_Byrack_Enable_IMM13_14 : 24|2@1+ (1,0) [0|3] ""  IMM
 SG_ M2I_Byrack_ReVeEnable_IMM13_14 : 26|2@1+ (1,0) [0|3] ""  IMM
 SG_ Reserved_14 : 28|4@1+ (1,0) [0|15] ""  IMM
 SG_ M2I_Byrack_IsPostTm_IMM13_14 : 32|8@1+ (0.01,0) [0|2.55] "s"  IMM
 SG_ M2I_Byrack_SysABStTm_IMM13_14 : 40|16@1+ (0.01,0) [0|655.35] "s"  IMM
 SG_ Reserved_14 : 56|8@1+ (1,0) [0|255] ""  IMM

BO_ 2332110239 M2I_Byrack_SUMDATA13__15: 8 MBMU
 SG_ CRC_M2I_Byrack_IMM13_15 : 0|8@1+ (1,0) [0|255] ""  IMM
 SG_ M2I_Byrack_HVS__IMM13_15 : 8|16@1+ (0.1,0) [0|6553.5] "v"  IMM
 SG_ M2I_Byrack_Enable_IMM13_15 : 24|2@1+ (1,0) [0|3] ""  IMM
 SG_ M2I_Byrack_ReVeEnable_IMM13_15 : 26|2@1+ (1,0) [0|3] ""  IMM
 SG_ Reserved_15 : 28|4@1+ (1,0) [0|15] ""  IMM
 SG_ M2I_Byrack_IsPostTm_IMM13_15 : 32|8@1+ (0.01,0) [0|2.55] "s"  IMM
 SG_ M2I_Byrack_SysABStTm_IMM13_15 : 40|16@1+ (0.01,0) [0|655.35] "s"  IMM
 SG_ Reserved_15 : 56|8@1+ (1,0) [0|255] ""  IMM

BO_ 2332110240 M2I_Byrack_SUMDATA13__16: 8 MBMU
 SG_ CRC_M2I_Byrack_IMM13_16 : 0|8@1+ (1,0) [0|255] ""  IMM
 SG_ M2I_Byrack_HVS__IMM13_16 : 8|16@1+ (0.1,0) [0|6553.5] "v"  IMM
 SG_ M2I_Byrack_Enable_IMM13_16 : 24|2@1+ (1,0) [0|3] ""  IMM
 SG_ M2I_Byrack_ReVeEnable_IMM13_16 : 26|2@1+ (1,0) [0|3] ""  IMM
 SG_ Reserved_16 : 28|4@1+ (1,0) [0|15] ""  IMM
 SG_ M2I_Byrack_IsPostTm_IMM13_16 : 32|8@1+ (0.01,0) [0|2.55] "s"  IMM
 SG_ M2I_Byrack_SysABStTm_IMM13_16 : 40|16@1+ (0.01,0) [0|655.35] "s"  IMM
 SG_ Reserved_16 : 56|8@1+ (1,0) [0|255] ""  IMM

BO_ 2332110241 M2I_Byrack_SUMDATA13__17: 8 MBMU
 SG_ CRC_M2I_Byrack_IMM13_17 : 0|8@1+ (1,0) [0|255] ""  IMM
 SG_ M2I_Byrack_HVS__IMM13_17 : 8|16@1+ (0.1,0) [0|6553.5] "v"  IMM
 SG_ M2I_Byrack_Enable_IMM13_17 : 24|2@1+ (1,0) [0|3] ""  IMM
 SG_ M2I_Byrack_ReVeEnable_IMM13_17 : 26|2@1+ (1,0) [0|3] ""  IMM
 SG_ Reserved_17 : 28|4@1+ (1,0) [0|15] ""  IMM
 SG_ M2I_Byrack_IsPostTm_IMM13_17 : 32|8@1+ (0.01,0) [0|2.55] "s"  IMM
 SG_ M2I_Byrack_SysABStTm_IMM13_17 : 40|16@1+ (0.01,0) [0|655.35] "s"  IMM
 SG_ Reserved_17 : 56|8@1+ (1,0) [0|255] ""  IMM

BO_ 2332110242 M2I_Byrack_SUMDATA13__18: 8 MBMU
 SG_ CRC_M2I_Byrack_IMM13_18 : 0|8@1+ (1,0) [0|255] ""  IMM
 SG_ M2I_Byrack_HVS__IMM13_18 : 8|16@1+ (0.1,0) [0|6553.5] "v"  IMM
 SG_ M2I_Byrack_Enable_IMM13_18 : 24|2@1+ (1,0) [0|3] ""  IMM
 SG_ M2I_Byrack_ReVeEnable_IMM13_18 : 26|2@1+ (1,0) [0|3] ""  IMM
 SG_ Reserved_18 : 28|4@1+ (1,0) [0|15] ""  IMM
 SG_ M2I_Byrack_IsPostTm_IMM13_18 : 32|8@1+ (0.01,0) [0|2.55] "s"  IMM
 SG_ M2I_Byrack_SysABStTm_IMM13_18 : 40|16@1+ (0.01,0) [0|655.35] "s"  IMM
 SG_ Reserved_18 : 56|8@1+ (1,0) [0|255] ""  IMM

BO_ 2332110243 M2I_Byrack_SUMDATA13__19: 8 MBMU
 SG_ CRC_M2I_Byrack_IMM13_19 : 0|8@1+ (1,0) [0|255] ""  IMM
 SG_ M2I_Byrack_HVS__IMM13_19 : 8|16@1+ (0.1,0) [0|6553.5] "v"  IMM
 SG_ M2I_Byrack_Enable_IMM13_19 : 24|2@1+ (1,0) [0|3] ""  IMM
 SG_ M2I_Byrack_ReVeEnable_IMM13_19 : 26|2@1+ (1,0) [0|3] ""  IMM
 SG_ Reserved_19 : 28|4@1+ (1,0) [0|15] ""  IMM
 SG_ M2I_Byrack_IsPostTm_IMM13_19 : 32|8@1+ (0.01,0) [0|2.55] "s"  IMM
 SG_ M2I_Byrack_SysABStTm_IMM13_19 : 40|16@1+ (0.01,0) [0|655.35] "s"  IMM
 SG_ Reserved_19 : 56|8@1+ (1,0) [0|255] ""  IMM

BO_ 2332110244 M2I_Byrack_SUMDATA13__20: 8 MBMU
 SG_ CRC_M2I_Byrack_IMM13_20 : 0|8@1+ (1,0) [0|255] ""  IMM
 SG_ M2I_Byrack_HVS__IMM13_20 : 8|16@1+ (0.1,0) [0|6553.5] "v"  IMM
 SG_ M2I_Byrack_Enable_IMM13_20 : 24|2@1+ (1,0) [0|3] ""  IMM
 SG_ M2I_Byrack_ReVeEnable_IMM13_20 : 26|2@1+ (1,0) [0|3] ""  IMM
 SG_ Reserved_20 : 28|4@1+ (1,0) [0|15] ""  IMM
 SG_ M2I_Byrack_IsPostTm_IMM13_20 : 32|8@1+ (0.01,0) [0|2.55] "s"  IMM
 SG_ M2I_Byrack_SysABStTm_IMM13_20 : 40|16@1+ (0.01,0) [0|655.35] "s"  IMM
 SG_ Reserved_20 : 56|8@1+ (1,0) [0|255] ""  IMM

BO_ 2332110245 M2I_Byrack_SUMDATA13__21: 8 MBMU
 SG_ CRC_M2I_Byrack_IMM13_21 : 0|8@1+ (1,0) [0|255] ""  IMM
 SG_ M2I_Byrack_HVS__IMM13_21 : 8|16@1+ (0.1,0) [0|6553.5] "v"  IMM
 SG_ M2I_Byrack_Enable_IMM13_21 : 24|2@1+ (1,0) [0|3] ""  IMM
 SG_ M2I_Byrack_ReVeEnable_IMM13_21 : 26|2@1+ (1,0) [0|3] ""  IMM
 SG_ Reserved_21 : 28|4@1+ (1,0) [0|15] ""  IMM
 SG_ M2I_Byrack_IsPostTm_IMM13_21 : 32|8@1+ (0.01,0) [0|2.55] "s"  IMM
 SG_ M2I_Byrack_SysABStTm_IMM13_21 : 40|16@1+ (0.01,0) [0|655.35] "s"  IMM
 SG_ Reserved_21 : 56|8@1+ (1,0) [0|255] ""  IMM

BO_ 2332110246 M2I_Byrack_SUMDATA13__22: 8 MBMU
 SG_ CRC_M2I_Byrack_IMM13_22 : 0|8@1+ (1,0) [0|255] ""  IMM
 SG_ M2I_Byrack_HVS__IMM13_22 : 8|16@1+ (0.1,0) [0|6553.5] "v"  IMM
 SG_ M2I_Byrack_Enable_IMM13_22 : 24|2@1+ (1,0) [0|3] ""  IMM
 SG_ M2I_Byrack_ReVeEnable_IMM13_22 : 26|2@1+ (1,0) [0|3] ""  IMM
 SG_ Reserved_22 : 28|4@1+ (1,0) [0|15] ""  IMM
 SG_ M2I_Byrack_IsPostTm_IMM13_22 : 32|8@1+ (0.01,0) [0|2.55] "s"  IMM
 SG_ M2I_Byrack_SysABStTm_IMM13_22 : 40|16@1+ (0.01,0) [0|655.35] "s"  IMM
 SG_ Reserved_22 : 56|8@1+ (1,0) [0|255] ""  IMM

BO_ 2332110247 M2I_Byrack_SUMDATA13__23: 8 MBMU
 SG_ CRC_M2I_Byrack_IMM13_23 : 0|8@1+ (1,0) [0|255] ""  IMM
 SG_ M2I_Byrack_HVS__IMM13_23 : 8|16@1+ (0.1,0) [0|6553.5] "v"  IMM
 SG_ M2I_Byrack_Enable_IMM13_23 : 24|2@1+ (1,0) [0|3] ""  IMM
 SG_ M2I_Byrack_ReVeEnable_IMM13_23 : 26|2@1+ (1,0) [0|3] ""  IMM
 SG_ Reserved_23 : 28|4@1+ (1,0) [0|15] ""  IMM
 SG_ M2I_Byrack_IsPostTm_IMM13_23 : 32|8@1+ (0.01,0) [0|2.55] "s"  IMM
 SG_ M2I_Byrack_SysABStTm_IMM13_23 : 40|16@1+ (0.01,0) [0|655.35] "s"  IMM
 SG_ Reserved_23 : 56|8@1+ (1,0) [0|255] ""  IMM

BO_ 2332110248 M2I_Byrack_SUMDATA13__24: 8 MBMU
 SG_ CRC_M2I_Byrack_IMM13_24 : 0|8@1+ (1,0) [0|255] ""  IMM
 SG_ M2I_Byrack_HVS__IMM13_24 : 8|16@1+ (0.1,0) [0|6553.5] "v"  IMM
 SG_ M2I_Byrack_Enable_IMM13_24 : 24|2@1+ (1,0) [0|3] ""  IMM
 SG_ M2I_Byrack_ReVeEnable_IMM13_24 : 26|2@1+ (1,0) [0|3] ""  IMM
 SG_ Reserved_24 : 28|4@1+ (1,0) [0|15] ""  IMM
 SG_ M2I_Byrack_IsPostTm_IMM13_24 : 32|8@1+ (0.01,0) [0|2.55] "s"  IMM
 SG_ M2I_Byrack_SysABStTm_IMM13_24 : 40|16@1+ (0.01,0) [0|655.35] "s"  IMM
 SG_ Reserved_24 : 56|8@1+ (1,0) [0|255] ""  IMM

BO_ 2332110249 M2I_Byrack_SUMDATA13__25: 8 MBMU
 SG_ CRC_M2I_Byrack_IMM13_25 : 0|8@1+ (1,0) [0|255] ""  IMM
 SG_ M2I_Byrack_HVS__IMM13_25 : 8|16@1+ (0.1,0) [0|6553.5] "v"  IMM
 SG_ M2I_Byrack_Enable_IMM13_25 : 24|2@1+ (1,0) [0|3] ""  IMM
 SG_ M2I_Byrack_ReVeEnable_IMM13_25 : 26|2@1+ (1,0) [0|3] ""  IMM
 SG_ Reserved_25 : 28|4@1+ (1,0) [0|15] ""  IMM
 SG_ M2I_Byrack_IsPostTm_IMM13_25 : 32|8@1+ (0.01,0) [0|2.55] "s"  IMM
 SG_ M2I_Byrack_SysABStTm_IMM13_25 : 40|16@1+ (0.01,0) [0|655.35] "s"  IMM
 SG_ Reserved_25 : 56|8@1+ (1,0) [0|255] ""  IMM

BO_ 2332110250 M2I_Byrack_SUMDATA13__26: 8 MBMU
 SG_ CRC_M2I_Byrack_IMM13_26 : 0|8@1+ (1,0) [0|255] ""  IMM
 SG_ M2I_Byrack_HVS__IMM13_26 : 8|16@1+ (0.1,0) [0|6553.5] "v"  IMM
 SG_ M2I_Byrack_Enable_IMM13_26 : 24|2@1+ (1,0) [0|3] ""  IMM
 SG_ M2I_Byrack_ReVeEnable_IMM13_26 : 26|2@1+ (1,0) [0|3] ""  IMM
 SG_ Reserved_26 : 28|4@1+ (1,0) [0|15] ""  IMM
 SG_ M2I_Byrack_IsPostTm_IMM13_26 : 32|8@1+ (0.01,0) [0|2.55] "s"  IMM
 SG_ M2I_Byrack_SysABStTm_IMM13_26 : 40|16@1+ (0.01,0) [0|655.35] "s"  IMM
 SG_ Reserved_26 : 56|8@1+ (1,0) [0|255] ""  IMM

BO_ 2332110251 M2I_Byrack_SUMDATA13__27: 8 MBMU
 SG_ CRC_M2I_Byrack_IMM13_27 : 0|8@1+ (1,0) [0|255] ""  IMM
 SG_ M2I_Byrack_HVS__IMM13_27 : 8|16@1+ (0.1,0) [0|6553.5] "v"  IMM
 SG_ M2I_Byrack_Enable_IMM13_27 : 24|2@1+ (1,0) [0|3] ""  IMM
 SG_ M2I_Byrack_ReVeEnable_IMM13_27 : 26|2@1+ (1,0) [0|3] ""  IMM
 SG_ Reserved_27 : 28|4@1+ (1,0) [0|15] ""  IMM
 SG_ M2I_Byrack_IsPostTm_IMM13_27 : 32|8@1+ (0.01,0) [0|2.55] "s"  IMM
 SG_ M2I_Byrack_SysABStTm_IMM13_27 : 40|16@1+ (0.01,0) [0|655.35] "s"  IMM
 SG_ Reserved_27 : 56|8@1+ (1,0) [0|255] ""  IMM

BO_ 2332110252 M2I_Byrack_SUMDATA13__28: 8 MBMU
 SG_ CRC_M2I_Byrack_IMM13_28 : 0|8@1+ (1,0) [0|255] ""  IMM
 SG_ M2I_Byrack_HVS__IMM13_28 : 8|16@1+ (0.1,0) [0|6553.5] "v"  IMM
 SG_ M2I_Byrack_Enable_IMM13_28 : 24|2@1+ (1,0) [0|3] ""  IMM
 SG_ M2I_Byrack_ReVeEnable_IMM13_28 : 26|2@1+ (1,0) [0|3] ""  IMM
 SG_ Reserved_28 : 28|4@1+ (1,0) [0|15] ""  IMM
 SG_ M2I_Byrack_IsPostTm_IMM13_28 : 32|8@1+ (0.01,0) [0|2.55] "s"  IMM
 SG_ M2I_Byrack_SysABStTm_IMM13_28 : 40|16@1+ (0.01,0) [0|655.35] "s"  IMM
 SG_ Reserved_28 : 56|8@1+ (1,0) [0|255] ""  IMM

BO_ 2332110253 M2I_Byrack_SUMDATA13__29: 8 MBMU
 SG_ CRC_M2I_Byrack_IMM13_29 : 0|8@1+ (1,0) [0|255] ""  IMM
 SG_ M2I_Byrack_HVS__IMM13_29 : 8|16@1+ (0.1,0) [0|6553.5] "v"  IMM
 SG_ M2I_Byrack_Enable_IMM13_29 : 24|2@1+ (1,0) [0|3] ""  IMM
 SG_ M2I_Byrack_ReVeEnable_IMM13_29 : 26|2@1+ (1,0) [0|3] ""  IMM
 SG_ Reserved_29 : 28|4@1+ (1,0) [0|15] ""  IMM
 SG_ M2I_Byrack_IsPostTm_IMM13_29 : 32|8@1+ (0.01,0) [0|2.55] "s"  IMM
 SG_ M2I_Byrack_SysABStTm_IMM13_29 : 40|16@1+ (0.01,0) [0|655.35] "s"  IMM
 SG_ Reserved_29 : 56|8@1+ (1,0) [0|255] ""  IMM

BO_ 2332110254 M2I_Byrack_SUMDATA13__30: 8 MBMU
 SG_ CRC_M2I_Byrack_IMM13_30 : 0|8@1+ (1,0) [0|255] ""  IMM
 SG_ M2I_Byrack_HVS__IMM13_30 : 8|16@1+ (0.1,0) [0|6553.5] "v"  IMM
 SG_ M2I_Byrack_Enable_IMM13_30 : 24|2@1+ (1,0) [0|3] ""  IMM
 SG_ M2I_Byrack_ReVeEnable_IMM13_30 : 26|2@1+ (1,0) [0|3] ""  IMM
 SG_ Reserved_30 : 28|4@1+ (1,0) [0|15] ""  IMM
 SG_ M2I_Byrack_IsPostTm_IMM13_30 : 32|8@1+ (0.01,0) [0|2.55] "s"  IMM
 SG_ M2I_Byrack_SysABStTm_IMM13_30 : 40|16@1+ (0.01,0) [0|655.35] "s"  IMM
 SG_ Reserved_30 : 56|8@1+ (1,0) [0|255] ""  IMM

BO_ 2332110255 M2I_Byrack_SUMDATA13__31: 8 MBMU
 SG_ CRC_M2I_Byrack_IMM13_31 : 0|8@1+ (1,0) [0|255] ""  IMM
 SG_ M2I_Byrack_HVS__IMM13_31 : 8|16@1+ (0.1,0) [0|6553.5] "v"  IMM
 SG_ M2I_Byrack_Enable_IMM13_31 : 24|2@1+ (1,0) [0|3] ""  IMM
 SG_ M2I_Byrack_ReVeEnable_IMM13_31 : 26|2@1+ (1,0) [0|3] ""  IMM
 SG_ Reserved_31 : 28|4@1+ (1,0) [0|15] ""  IMM
 SG_ M2I_Byrack_IsPostTm_IMM13_31 : 32|8@1+ (0.01,0) [0|2.55] "s"  IMM
 SG_ M2I_Byrack_SysABStTm_IMM13_31 : 40|16@1+ (0.01,0) [0|655.35] "s"  IMM
 SG_ Reserved_31 : 56|8@1+ (1,0) [0|255] ""  IMM

BO_ 2332110481 M2I_Byrack_SUMDATA14__01: 8 MBMU
 SG_ CRC_M2I_Byrack_IMM14_01 : 0|8@1+ (1,0) [0|255] ""  IMM
 SG_ M2I_Byrack_HVS_IMM14_01 : 8|16@1+ (0.1,0) [0|6553.5] "v"  IMM
 SG_ M2I_Byrack_Enable_IMM14_01 : 24|2@1+ (1,0) [0|3] ""  IMM
 SG_ M2I_Byrack_ReVeEnable_IMM14_01 : 26|2@1+ (1,0) [0|3] ""  IMM
 SG_ Reserved_01 : 28|4@1+ (1,0) [0|15] ""  IMM
 SG_ M2I_Byrack_IsPostTm_IMM14_01 : 32|8@1+ (0.01,0) [0|2.55] "s"  IMM
 SG_ M2I_Byrack_SysABStTm_IMM14_01 : 40|16@1+ (0.01,0) [0|655.35] "s"  IMM
 SG_ Reserved_01 : 56|8@1+ (1,0) [0|255] ""  IMM

BO_ 2332110482 M2I_Byrack_SUMDATA14__02: 8 MBMU
 SG_ CRC_M2I_Byrack_IMM14_02 : 0|8@1+ (1,0) [0|255] ""  IMM
 SG_ M2I_Byrack_HVS_IMM14_02 : 8|16@1+ (0.1,0) [0|6553.5] "v"  IMM
 SG_ M2I_Byrack_Enable_IMM14_02 : 24|2@1+ (1,0) [0|3] ""  IMM
 SG_ M2I_Byrack_ReVeEnable_IMM14_02 : 26|2@1+ (1,0) [0|3] ""  IMM
 SG_ Reserved_02 : 28|4@1+ (1,0) [0|15] ""  IMM
 SG_ M2I_Byrack_IsPostTm_IMM14_02 : 32|8@1+ (0.01,0) [0|2.55] "s"  IMM
 SG_ M2I_Byrack_SysABStTm_IMM14_02 : 40|16@1+ (0.01,0) [0|655.35] "s"  IMM
 SG_ Reserved_02 : 56|8@1+ (1,0) [0|255] ""  IMM

BO_ 2332110483 M2I_Byrack_SUMDATA14__03: 8 MBMU
 SG_ CRC_M2I_Byrack_IMM14_03 : 0|8@1+ (1,0) [0|255] ""  IMM
 SG_ M2I_Byrack_HVS_IMM14_03 : 8|16@1+ (0.1,0) [0|6553.5] "v"  IMM
 SG_ M2I_Byrack_Enable_IMM14_03 : 24|2@1+ (1,0) [0|3] ""  IMM
 SG_ M2I_Byrack_ReVeEnable_IMM14_03 : 26|2@1+ (1,0) [0|3] ""  IMM
 SG_ Reserved_03 : 28|4@1+ (1,0) [0|15] ""  IMM
 SG_ M2I_Byrack_IsPostTm_IMM14_03 : 32|8@1+ (0.01,0) [0|2.55] "s"  IMM
 SG_ M2I_Byrack_SysABStTm_IMM14_03 : 40|16@1+ (0.01,0) [0|655.35] "s"  IMM
 SG_ Reserved_03 : 56|8@1+ (1,0) [0|255] ""  IMM

BO_ 2332110484 M2I_Byrack_SUMDATA14__04: 8 MBMU
 SG_ CRC_M2I_Byrack_IMM14_04 : 0|8@1+ (1,0) [0|255] ""  IMM
 SG_ M2I_Byrack_HVS_IMM14_04 : 8|16@1+ (0.1,0) [0|6553.5] "v"  IMM
 SG_ M2I_Byrack_Enable_IMM14_04 : 24|2@1+ (1,0) [0|3] ""  IMM
 SG_ M2I_Byrack_ReVeEnable_IMM14_04 : 26|2@1+ (1,0) [0|3] ""  IMM
 SG_ Reserved_04 : 28|4@1+ (1,0) [0|15] ""  IMM
 SG_ M2I_Byrack_IsPostTm_IMM14_04 : 32|8@1+ (0.01,0) [0|2.55] "s"  IMM
 SG_ M2I_Byrack_SysABStTm_IMM14_04 : 40|16@1+ (0.01,0) [0|655.35] "s"  IMM
 SG_ Reserved_04 : 56|8@1+ (1,0) [0|255] ""  IMM

BO_ 2332110485 M2I_Byrack_SUMDATA14__05: 8 MBMU
 SG_ CRC_M2I_Byrack_IMM14_05 : 0|8@1+ (1,0) [0|255] ""  IMM
 SG_ M2I_Byrack_HVS_IMM14_05 : 8|16@1+ (0.1,0) [0|6553.5] "v"  IMM
 SG_ M2I_Byrack_Enable_IMM14_05 : 24|2@1+ (1,0) [0|3] ""  IMM
 SG_ M2I_Byrack_ReVeEnable_IMM14_05 : 26|2@1+ (1,0) [0|3] ""  IMM
 SG_ Reserved_05 : 28|4@1+ (1,0) [0|15] ""  IMM
 SG_ M2I_Byrack_IsPostTm_IMM14_05 : 32|8@1+ (0.01,0) [0|2.55] "s"  IMM
 SG_ M2I_Byrack_SysABStTm_IMM14_05 : 40|16@1+ (0.01,0) [0|655.35] "s"  IMM
 SG_ Reserved_05 : 56|8@1+ (1,0) [0|255] ""  IMM

BO_ 2332110486 M2I_Byrack_SUMDATA14__06: 8 MBMU
 SG_ CRC_M2I_Byrack_IMM14_06 : 0|8@1+ (1,0) [0|255] ""  IMM
 SG_ M2I_Byrack_HVS_IMM14_06 : 8|16@1+ (0.1,0) [0|6553.5] "v"  IMM
 SG_ M2I_Byrack_Enable_IMM14_06 : 24|2@1+ (1,0) [0|3] ""  IMM
 SG_ M2I_Byrack_ReVeEnable_IMM14_06 : 26|2@1+ (1,0) [0|3] ""  IMM
 SG_ Reserved_06 : 28|4@1+ (1,0) [0|15] ""  IMM
 SG_ M2I_Byrack_IsPostTm_IMM14_06 : 32|8@1+ (0.01,0) [0|2.55] "s"  IMM
 SG_ M2I_Byrack_SysABStTm_IMM14_06 : 40|16@1+ (0.01,0) [0|655.35] "s"  IMM
 SG_ Reserved_06 : 56|8@1+ (1,0) [0|255] ""  IMM

BO_ 2332110487 M2I_Byrack_SUMDATA14__07: 8 MBMU
 SG_ CRC_M2I_Byrack_IMM14_07 : 0|8@1+ (1,0) [0|255] ""  IMM
 SG_ M2I_Byrack_HVS_IMM14_07 : 8|16@1+ (0.1,0) [0|6553.5] "v"  IMM
 SG_ M2I_Byrack_Enable_IMM14_07 : 24|2@1+ (1,0) [0|3] ""  IMM
 SG_ M2I_Byrack_ReVeEnable_IMM14_07 : 26|2@1+ (1,0) [0|3] ""  IMM
 SG_ Reserved_07 : 28|4@1+ (1,0) [0|15] ""  IMM
 SG_ M2I_Byrack_IsPostTm_IMM14_07 : 32|8@1+ (0.01,0) [0|2.55] "s"  IMM
 SG_ M2I_Byrack_SysABStTm_IMM14_07 : 40|16@1+ (0.01,0) [0|655.35] "s"  IMM
 SG_ Reserved_07 : 56|8@1+ (1,0) [0|255] ""  IMM

BO_ 2332110488 M2I_Byrack_SUMDATA14__08: 8 MBMU
 SG_ CRC_M2I_Byrack_IMM14_08 : 0|8@1+ (1,0) [0|255] ""  IMM
 SG_ M2I_Byrack_HVS_IMM14_08 : 8|16@1+ (0.1,0) [0|6553.5] "v"  IMM
 SG_ M2I_Byrack_Enable_IMM14_08 : 24|2@1+ (1,0) [0|3] ""  IMM
 SG_ M2I_Byrack_ReVeEnable_IMM14_08 : 26|2@1+ (1,0) [0|3] ""  IMM
 SG_ Reserved_08 : 28|4@1+ (1,0) [0|15] ""  IMM
 SG_ M2I_Byrack_IsPostTm_IMM14_08 : 32|8@1+ (0.01,0) [0|2.55] "s"  IMM
 SG_ M2I_Byrack_SysABStTm_IMM14_08 : 40|16@1+ (0.01,0) [0|655.35] "s"  IMM
 SG_ Reserved_08 : 56|8@1+ (1,0) [0|255] ""  IMM

BO_ 2332110489 M2I_Byrack_SUMDATA14__09: 8 MBMU
 SG_ CRC_M2I_Byrack_IMM14_09 : 0|8@1+ (1,0) [0|255] ""  IMM
 SG_ M2I_Byrack_HVS_IMM14_09 : 8|16@1+ (0.1,0) [0|6553.5] "v"  IMM
 SG_ M2I_Byrack_Enable_IMM14_09 : 24|2@1+ (1,0) [0|3] ""  IMM
 SG_ M2I_Byrack_ReVeEnable_IMM14_09 : 26|2@1+ (1,0) [0|3] ""  IMM
 SG_ Reserved_09 : 28|4@1+ (1,0) [0|15] ""  IMM
 SG_ M2I_Byrack_IsPostTm_IMM14_09 : 32|8@1+ (0.01,0) [0|2.55] "s"  IMM
 SG_ M2I_Byrack_SysABStTm_IMM14_09 : 40|16@1+ (0.01,0) [0|655.35] "s"  IMM
 SG_ Reserved_09 : 56|8@1+ (1,0) [0|255] ""  IMM

BO_ 2332110490 M2I_Byrack_SUMDATA14__10: 8 MBMU
 SG_ CRC_M2I_Byrack_IMM14_10 : 0|8@1+ (1,0) [0|255] ""  IMM
 SG_ M2I_Byrack_HVS_IMM14_10 : 8|16@1+ (0.1,0) [0|6553.5] "v"  IMM
 SG_ M2I_Byrack_Enable_IMM14_10 : 24|2@1+ (1,0) [0|3] ""  IMM
 SG_ M2I_Byrack_ReVeEnable_IMM14_10 : 26|2@1+ (1,0) [0|3] ""  IMM
 SG_ Reserved_10 : 28|4@1+ (1,0) [0|15] ""  IMM
 SG_ M2I_Byrack_IsPostTm_IMM14_10 : 32|8@1+ (0.01,0) [0|2.55] "s"  IMM
 SG_ M2I_Byrack_SysABStTm_IMM14_10 : 40|16@1+ (0.01,0) [0|655.35] "s"  IMM
 SG_ Reserved_10 : 56|8@1+ (1,0) [0|255] ""  IMM

BO_ 2332110491 M2I_Byrack_SUMDATA14__11: 8 MBMU
 SG_ CRC_M2I_Byrack_IMM14_11 : 0|8@1+ (1,0) [0|255] ""  IMM
 SG_ M2I_Byrack_HVS_IMM14_11 : 8|16@1+ (0.1,0) [0|6553.5] "v"  IMM
 SG_ M2I_Byrack_Enable_IMM14_11 : 24|2@1+ (1,0) [0|3] ""  IMM
 SG_ M2I_Byrack_ReVeEnable_IMM14_11 : 26|2@1+ (1,0) [0|3] ""  IMM
 SG_ Reserved_11 : 28|4@1+ (1,0) [0|15] ""  IMM
 SG_ M2I_Byrack_IsPostTm_IMM14_11 : 32|8@1+ (0.01,0) [0|2.55] "s"  IMM
 SG_ M2I_Byrack_SysABStTm_IMM14_11 : 40|16@1+ (0.01,0) [0|655.35] "s"  IMM
 SG_ Reserved_11 : 56|8@1+ (1,0) [0|255] ""  IMM

BO_ 2332110492 M2I_Byrack_SUMDATA14__12: 8 MBMU
 SG_ CRC_M2I_Byrack_IMM14_12 : 0|8@1+ (1,0) [0|255] ""  IMM
 SG_ M2I_Byrack_HVS_IMM14_12 : 8|16@1+ (0.1,0) [0|6553.5] "v"  IMM
 SG_ M2I_Byrack_Enable_IMM14_12 : 24|2@1+ (1,0) [0|3] ""  IMM
 SG_ M2I_Byrack_ReVeEnable_IMM14_12 : 26|2@1+ (1,0) [0|3] ""  IMM
 SG_ Reserved_12 : 28|4@1+ (1,0) [0|15] ""  IMM
 SG_ M2I_Byrack_IsPostTm_IMM14_12 : 32|8@1+ (0.01,0) [0|2.55] "s"  IMM
 SG_ M2I_Byrack_SysABStTm_IMM14_12 : 40|16@1+ (0.01,0) [0|655.35] "s"  IMM
 SG_ Reserved_12 : 56|8@1+ (1,0) [0|255] ""  IMM

BO_ 2332110493 M2I_Byrack_SUMDATA14__13: 8 MBMU
 SG_ CRC_M2I_Byrack_IMM14_13 : 0|8@1+ (1,0) [0|255] ""  IMM
 SG_ M2I_Byrack_HVS_IMM14_13 : 8|16@1+ (0.1,0) [0|6553.5] "v"  IMM
 SG_ M2I_Byrack_Enable_IMM14_13 : 24|2@1+ (1,0) [0|3] ""  IMM
 SG_ M2I_Byrack_ReVeEnable_IMM14_13 : 26|2@1+ (1,0) [0|3] ""  IMM
 SG_ Reserved_13 : 28|4@1+ (1,0) [0|15] ""  IMM
 SG_ M2I_Byrack_IsPostTm_IMM14_13 : 32|8@1+ (0.01,0) [0|2.55] "s"  IMM
 SG_ M2I_Byrack_SysABStTm_IMM14_13 : 40|16@1+ (0.01,0) [0|655.35] "s"  IMM
 SG_ Reserved_13 : 56|8@1+ (1,0) [0|255] ""  IMM

BO_ 2332110494 M2I_Byrack_SUMDATA14__14: 8 MBMU
 SG_ CRC_M2I_Byrack_IMM14_14 : 0|8@1+ (1,0) [0|255] ""  IMM
 SG_ M2I_Byrack_HVS_IMM14_14 : 8|16@1+ (0.1,0) [0|6553.5] "v"  IMM
 SG_ M2I_Byrack_Enable_IMM14_14 : 24|2@1+ (1,0) [0|3] ""  IMM
 SG_ M2I_Byrack_ReVeEnable_IMM14_14 : 26|2@1+ (1,0) [0|3] ""  IMM
 SG_ Reserved_14 : 28|4@1+ (1,0) [0|15] ""  IMM
 SG_ M2I_Byrack_IsPostTm_IMM14_14 : 32|8@1+ (0.01,0) [0|2.55] "s"  IMM
 SG_ M2I_Byrack_SysABStTm_IMM14_14 : 40|16@1+ (0.01,0) [0|655.35] "s"  IMM
 SG_ Reserved_14 : 56|8@1+ (1,0) [0|255] ""  IMM

BO_ 2332110495 M2I_Byrack_SUMDATA14__15: 8 MBMU
 SG_ CRC_M2I_Byrack_IMM14_15 : 0|8@1+ (1,0) [0|255] ""  IMM
 SG_ M2I_Byrack_HVS_IMM14_15 : 8|16@1+ (0.1,0) [0|6553.5] "v"  IMM
 SG_ M2I_Byrack_Enable_IMM14_15 : 24|2@1+ (1,0) [0|3] ""  IMM
 SG_ M2I_Byrack_ReVeEnable_IMM14_15 : 26|2@1+ (1,0) [0|3] ""  IMM
 SG_ Reserved_15 : 28|4@1+ (1,0) [0|15] ""  IMM
 SG_ M2I_Byrack_IsPostTm_IMM14_15 : 32|8@1+ (0.01,0) [0|2.55] "s"  IMM
 SG_ M2I_Byrack_SysABStTm_IMM14_15 : 40|16@1+ (0.01,0) [0|655.35] "s"  IMM
 SG_ Reserved_15 : 56|8@1+ (1,0) [0|255] ""  IMM

BO_ 2332110496 M2I_Byrack_SUMDATA14__16: 8 MBMU
 SG_ CRC_M2I_Byrack_IMM14_16 : 0|8@1+ (1,0) [0|255] ""  IMM
 SG_ M2I_Byrack_HVS_IMM14_16 : 8|16@1+ (0.1,0) [0|6553.5] "v"  IMM
 SG_ M2I_Byrack_Enable_IMM14_16 : 24|2@1+ (1,0) [0|3] ""  IMM
 SG_ M2I_Byrack_ReVeEnable_IMM14_16 : 26|2@1+ (1,0) [0|3] ""  IMM
 SG_ Reserved_16 : 28|4@1+ (1,0) [0|15] ""  IMM
 SG_ M2I_Byrack_IsPostTm_IMM14_16 : 32|8@1+ (0.01,0) [0|2.55] "s"  IMM
 SG_ M2I_Byrack_SysABStTm_IMM14_16 : 40|16@1+ (0.01,0) [0|655.35] "s"  IMM
 SG_ Reserved_16 : 56|8@1+ (1,0) [0|255] ""  IMM

BO_ 2332110497 M2I_Byrack_SUMDATA14__17: 8 MBMU
 SG_ CRC_M2I_Byrack_IMM14_17 : 0|8@1+ (1,0) [0|255] ""  IMM
 SG_ M2I_Byrack_HVS_IMM14_17 : 8|16@1+ (0.1,0) [0|6553.5] "v"  IMM
 SG_ M2I_Byrack_Enable_IMM14_17 : 24|2@1+ (1,0) [0|3] ""  IMM
 SG_ M2I_Byrack_ReVeEnable_IMM14_17 : 26|2@1+ (1,0) [0|3] ""  IMM
 SG_ Reserved_17 : 28|4@1+ (1,0) [0|15] ""  IMM
 SG_ M2I_Byrack_IsPostTm_IMM14_17 : 32|8@1+ (0.01,0) [0|2.55] "s"  IMM
 SG_ M2I_Byrack_SysABStTm_IMM14_17 : 40|16@1+ (0.01,0) [0|655.35] "s"  IMM
 SG_ Reserved_17 : 56|8@1+ (1,0) [0|255] ""  IMM

BO_ 2332110498 M2I_Byrack_SUMDATA14__18: 8 MBMU
 SG_ CRC_M2I_Byrack_IMM14_18 : 0|8@1+ (1,0) [0|255] ""  IMM
 SG_ M2I_Byrack_HVS_IMM14_18 : 8|16@1+ (0.1,0) [0|6553.5] "v"  IMM
 SG_ M2I_Byrack_Enable_IMM14_18 : 24|2@1+ (1,0) [0|3] ""  IMM
 SG_ M2I_Byrack_ReVeEnable_IMM14_18 : 26|2@1+ (1,0) [0|3] ""  IMM
 SG_ Reserved_18 : 28|4@1+ (1,0) [0|15] ""  IMM
 SG_ M2I_Byrack_IsPostTm_IMM14_18 : 32|8@1+ (0.01,0) [0|2.55] "s"  IMM
 SG_ M2I_Byrack_SysABStTm_IMM14_18 : 40|16@1+ (0.01,0) [0|655.35] "s"  IMM
 SG_ Reserved_18 : 56|8@1+ (1,0) [0|255] ""  IMM

BO_ 2332110499 M2I_Byrack_SUMDATA14__19: 8 MBMU
 SG_ CRC_M2I_Byrack_IMM14_19 : 0|8@1+ (1,0) [0|255] ""  IMM
 SG_ M2I_Byrack_HVS_IMM14_19 : 8|16@1+ (0.1,0) [0|6553.5] "v"  IMM
 SG_ M2I_Byrack_Enable_IMM14_19 : 24|2@1+ (1,0) [0|3] ""  IMM
 SG_ M2I_Byrack_ReVeEnable_IMM14_19 : 26|2@1+ (1,0) [0|3] ""  IMM
 SG_ Reserved_19 : 28|4@1+ (1,0) [0|15] ""  IMM
 SG_ M2I_Byrack_IsPostTm_IMM14_19 : 32|8@1+ (0.01,0) [0|2.55] "s"  IMM
 SG_ M2I_Byrack_SysABStTm_IMM14_19 : 40|16@1+ (0.01,0) [0|655.35] "s"  IMM
 SG_ Reserved_19 : 56|8@1+ (1,0) [0|255] ""  IMM

BO_ 2332110500 M2I_Byrack_SUMDATA14__20: 8 MBMU
 SG_ CRC_M2I_Byrack_IMM14_20 : 0|8@1+ (1,0) [0|255] ""  IMM
 SG_ M2I_Byrack_HVS_IMM14_20 : 8|16@1+ (0.1,0) [0|6553.5] "v"  IMM
 SG_ M2I_Byrack_Enable_IMM14_20 : 24|2@1+ (1,0) [0|3] ""  IMM
 SG_ M2I_Byrack_ReVeEnable_IMM14_20 : 26|2@1+ (1,0) [0|3] ""  IMM
 SG_ Reserved_20 : 28|4@1+ (1,0) [0|15] ""  IMM
 SG_ M2I_Byrack_IsPostTm_IMM14_20 : 32|8@1+ (0.01,0) [0|2.55] "s"  IMM
 SG_ M2I_Byrack_SysABStTm_IMM14_20 : 40|16@1+ (0.01,0) [0|655.35] "s"  IMM
 SG_ Reserved_20 : 56|8@1+ (1,0) [0|255] ""  IMM

BO_ 2332110501 M2I_Byrack_SUMDATA14__21: 8 MBMU
 SG_ CRC_M2I_Byrack_IMM14_21 : 0|8@1+ (1,0) [0|255] ""  IMM
 SG_ M2I_Byrack_HVS_IMM14_21 : 8|16@1+ (0.1,0) [0|6553.5] "v"  IMM
 SG_ M2I_Byrack_Enable_IMM14_21 : 24|2@1+ (1,0) [0|3] ""  IMM
 SG_ M2I_Byrack_ReVeEnable_IMM14_21 : 26|2@1+ (1,0) [0|3] ""  IMM
 SG_ Reserved_21 : 28|4@1+ (1,0) [0|15] ""  IMM
 SG_ M2I_Byrack_IsPostTm_IMM14_21 : 32|8@1+ (0.01,0) [0|2.55] "s"  IMM
 SG_ M2I_Byrack_SysABStTm_IMM14_21 : 40|16@1+ (0.01,0) [0|655.35] "s"  IMM
 SG_ Reserved_21 : 56|8@1+ (1,0) [0|255] ""  IMM

BO_ 2332110502 M2I_Byrack_SUMDATA14__22: 8 MBMU
 SG_ CRC_M2I_Byrack_IMM14_22 : 0|8@1+ (1,0) [0|255] ""  IMM
 SG_ M2I_Byrack_HVS_IMM14_22 : 8|16@1+ (0.1,0) [0|6553.5] "v"  IMM
 SG_ M2I_Byrack_Enable_IMM14_22 : 24|2@1+ (1,0) [0|3] ""  IMM
 SG_ M2I_Byrack_ReVeEnable_IMM14_22 : 26|2@1+ (1,0) [0|3] ""  IMM
 SG_ Reserved_22 : 28|4@1+ (1,0) [0|15] ""  IMM
 SG_ M2I_Byrack_IsPostTm_IMM14_22 : 32|8@1+ (0.01,0) [0|2.55] "s"  IMM
 SG_ M2I_Byrack_SysABStTm_IMM14_22 : 40|16@1+ (0.01,0) [0|655.35] "s"  IMM
 SG_ Reserved_22 : 56|8@1+ (1,0) [0|255] ""  IMM

BO_ 2332110503 M2I_Byrack_SUMDATA14__23: 8 MBMU
 SG_ CRC_M2I_Byrack_IMM14_23 : 0|8@1+ (1,0) [0|255] ""  IMM
 SG_ M2I_Byrack_HVS_IMM14_23 : 8|16@1+ (0.1,0) [0|6553.5] "v"  IMM
 SG_ M2I_Byrack_Enable_IMM14_23 : 24|2@1+ (1,0) [0|3] ""  IMM
 SG_ M2I_Byrack_ReVeEnable_IMM14_23 : 26|2@1+ (1,0) [0|3] ""  IMM
 SG_ Reserved_23 : 28|4@1+ (1,0) [0|15] ""  IMM
 SG_ M2I_Byrack_IsPostTm_IMM14_23 : 32|8@1+ (0.01,0) [0|2.55] "s"  IMM
 SG_ M2I_Byrack_SysABStTm_IMM14_23 : 40|16@1+ (0.01,0) [0|655.35] "s"  IMM
 SG_ Reserved_23 : 56|8@1+ (1,0) [0|255] ""  IMM

BO_ 2332110504 M2I_Byrack_SUMDATA14__24: 8 MBMU
 SG_ CRC_M2I_Byrack_IMM14_24 : 0|8@1+ (1,0) [0|255] ""  IMM
 SG_ M2I_Byrack_HVS_IMM14_24 : 8|16@1+ (0.1,0) [0|6553.5] "v"  IMM
 SG_ M2I_Byrack_Enable_IMM14_24 : 24|2@1+ (1,0) [0|3] ""  IMM
 SG_ M2I_Byrack_ReVeEnable_IMM14_24 : 26|2@1+ (1,0) [0|3] ""  IMM
 SG_ Reserved_24 : 28|4@1+ (1,0) [0|15] ""  IMM
 SG_ M2I_Byrack_IsPostTm_IMM14_24 : 32|8@1+ (0.01,0) [0|2.55] "s"  IMM
 SG_ M2I_Byrack_SysABStTm_IMM14_24 : 40|16@1+ (0.01,0) [0|655.35] "s"  IMM
 SG_ Reserved_24 : 56|8@1+ (1,0) [0|255] ""  IMM

BO_ 2332110505 M2I_Byrack_SUMDATA14__25: 8 MBMU
 SG_ CRC_M2I_Byrack_IMM14_25 : 0|8@1+ (1,0) [0|255] ""  IMM
 SG_ M2I_Byrack_HVS_IMM14_25 : 8|16@1+ (0.1,0) [0|6553.5] "v"  IMM
 SG_ M2I_Byrack_Enable_IMM14_25 : 24|2@1+ (1,0) [0|3] ""  IMM
 SG_ M2I_Byrack_ReVeEnable_IMM14_25 : 26|2@1+ (1,0) [0|3] ""  IMM
 SG_ Reserved_25 : 28|4@1+ (1,0) [0|15] ""  IMM
 SG_ M2I_Byrack_IsPostTm_IMM14_25 : 32|8@1+ (0.01,0) [0|2.55] "s"  IMM
 SG_ M2I_Byrack_SysABStTm_IMM14_25 : 40|16@1+ (0.01,0) [0|655.35] "s"  IMM
 SG_ Reserved_25 : 56|8@1+ (1,0) [0|255] ""  IMM

BO_ 2332110506 M2I_Byrack_SUMDATA14__26: 8 MBMU
 SG_ CRC_M2I_Byrack_IMM14_26 : 0|8@1+ (1,0) [0|255] ""  IMM
 SG_ M2I_Byrack_HVS_IMM14_26 : 8|16@1+ (0.1,0) [0|6553.5] "v"  IMM
 SG_ M2I_Byrack_Enable_IMM14_26 : 24|2@1+ (1,0) [0|3] ""  IMM
 SG_ M2I_Byrack_ReVeEnable_IMM14_26 : 26|2@1+ (1,0) [0|3] ""  IMM
 SG_ Reserved_26 : 28|4@1+ (1,0) [0|15] ""  IMM
 SG_ M2I_Byrack_IsPostTm_IMM14_26 : 32|8@1+ (0.01,0) [0|2.55] "s"  IMM
 SG_ M2I_Byrack_SysABStTm_IMM14_26 : 40|16@1+ (0.01,0) [0|655.35] "s"  IMM
 SG_ Reserved_26 : 56|8@1+ (1,0) [0|255] ""  IMM

BO_ 2332110507 M2I_Byrack_SUMDATA14__27: 8 MBMU
 SG_ CRC_M2I_Byrack_IMM14_27 : 0|8@1+ (1,0) [0|255] ""  IMM
 SG_ M2I_Byrack_HVS_IMM14_27 : 8|16@1+ (0.1,0) [0|6553.5] "v"  IMM
 SG_ M2I_Byrack_Enable_IMM14_27 : 24|2@1+ (1,0) [0|3] ""  IMM
 SG_ M2I_Byrack_ReVeEnable_IMM14_27 : 26|2@1+ (1,0) [0|3] ""  IMM
 SG_ Reserved_27 : 28|4@1+ (1,0) [0|15] ""  IMM
 SG_ M2I_Byrack_IsPostTm_IMM14_27 : 32|8@1+ (0.01,0) [0|2.55] "s"  IMM
 SG_ M2I_Byrack_SysABStTm_IMM14_27 : 40|16@1+ (0.01,0) [0|655.35] "s"  IMM
 SG_ Reserved_27 : 56|8@1+ (1,0) [0|255] ""  IMM

BO_ 2332110508 M2I_Byrack_SUMDATA14__28: 8 MBMU
 SG_ CRC_M2I_Byrack_IMM14_28 : 0|8@1+ (1,0) [0|255] ""  IMM
 SG_ M2I_Byrack_HVS_IMM14_28 : 8|16@1+ (0.1,0) [0|6553.5] "v"  IMM
 SG_ M2I_Byrack_Enable_IMM14_28 : 24|2@1+ (1,0) [0|3] ""  IMM
 SG_ M2I_Byrack_ReVeEnable_IMM14_28 : 26|2@1+ (1,0) [0|3] ""  IMM
 SG_ Reserved_28 : 28|4@1+ (1,0) [0|15] ""  IMM
 SG_ M2I_Byrack_IsPostTm_IMM14_28 : 32|8@1+ (0.01,0) [0|2.55] "s"  IMM
 SG_ M2I_Byrack_SysABStTm_IMM14_28 : 40|16@1+ (0.01,0) [0|655.35] "s"  IMM
 SG_ Reserved_28 : 56|8@1+ (1,0) [0|255] ""  IMM

BO_ 2332110509 M2I_Byrack_SUMDATA14__29: 8 MBMU
 SG_ CRC_M2I_Byrack_IMM14_29 : 0|8@1+ (1,0) [0|255] ""  IMM
 SG_ M2I_Byrack_HVS_IMM14_29 : 8|16@1+ (0.1,0) [0|6553.5] "v"  IMM
 SG_ M2I_Byrack_Enable_IMM14_29 : 24|2@1+ (1,0) [0|3] ""  IMM
 SG_ M2I_Byrack_ReVeEnable_IMM14_29 : 26|2@1+ (1,0) [0|3] ""  IMM
 SG_ Reserved_29 : 28|4@1+ (1,0) [0|15] ""  IMM
 SG_ M2I_Byrack_IsPostTm_IMM14_29 : 32|8@1+ (0.01,0) [0|2.55] "s"  IMM
 SG_ M2I_Byrack_SysABStTm_IMM14_29 : 40|16@1+ (0.01,0) [0|655.35] "s"  IMM
 SG_ Reserved_29 : 56|8@1+ (1,0) [0|255] ""  IMM

BO_ 2332110510 M2I_Byrack_SUMDATA14__30: 8 MBMU
 SG_ CRC_M2I_Byrack_IMM14_30 : 0|8@1+ (1,0) [0|255] ""  IMM
 SG_ M2I_Byrack_HVS_IMM14_30 : 8|16@1+ (0.1,0) [0|6553.5] "v"  IMM
 SG_ M2I_Byrack_Enable_IMM14_30 : 24|2@1+ (1,0) [0|3] ""  IMM
 SG_ M2I_Byrack_ReVeEnable_IMM14_30 : 26|2@1+ (1,0) [0|3] ""  IMM
 SG_ Reserved_30 : 28|4@1+ (1,0) [0|15] ""  IMM
 SG_ M2I_Byrack_IsPostTm_IMM14_30 : 32|8@1+ (0.01,0) [0|2.55] "s"  IMM
 SG_ M2I_Byrack_SysABStTm_IMM14_30 : 40|16@1+ (0.01,0) [0|655.35] "s"  IMM
 SG_ Reserved_30 : 56|8@1+ (1,0) [0|255] ""  IMM

BO_ 2332110511 M2I_Byrack_SUMDATA14__31: 8 MBMU
 SG_ CRC_M2I_Byrack_IMM14_31 : 0|8@1+ (1,0) [0|255] ""  IMM
 SG_ M2I_Byrack_HVS_IMM14_31 : 8|16@1+ (0.1,0) [0|6553.5] "v"  IMM
 SG_ M2I_Byrack_Enable_IMM14_31 : 24|2@1+ (1,0) [0|3] ""  IMM
 SG_ M2I_Byrack_ReVeEnable_IMM14_31 : 26|2@1+ (1,0) [0|3] ""  IMM
 SG_ Reserved_31 : 28|4@1+ (1,0) [0|15] ""  IMM
 SG_ M2I_Byrack_IsPostTm_IMM14_31 : 32|8@1+ (0.01,0) [0|2.55] "s"  IMM
 SG_ M2I_Byrack_SysABStTm_IMM14_31 : 40|16@1+ (0.01,0) [0|655.35] "s"  IMM
 SG_ Reserved_31 : 56|8@1+ (1,0) [0|255] ""  IMM

BO_ 2332110737 M2I_Byrack_SUMDATA15__01: 8 MBMU
 SG_ CRC_M2I_Byrack_IMM15_01 : 0|8@1+ (1,0) [0|255] ""  IMM
 SG_ M2I_Byrack_HVS_IMM15_01 : 8|16@1+ (0.1,0) [0|6553.5] "v"  IMM
 SG_ M2I_Byrack_Enable_IMM15_01 : 24|2@1+ (1,0) [0|3] ""  IMM
 SG_ M2I_Byrack_ReVeEnable_IMM15_01 : 26|2@1+ (1,0) [0|3] ""  IMM
 SG_ Reserved_01 : 28|4@1+ (1,0) [0|15] ""  IMM
 SG_ M2I_Byrack_IsPostTm_IMM15_01 : 32|8@1+ (0.01,0) [0|2.55] "s"  IMM
 SG_ M2I_Byrack_SysABStTm_IMM15_01 : 40|16@1+ (0.01,0) [0|655.35] "s"  IMM
 SG_ Reserved_01 : 56|8@1+ (1,0) [0|255] ""  IMM

BO_ 2332110738 M2I_Byrack_SUMDATA15__02: 8 MBMU
 SG_ CRC_M2I_Byrack_IMM15_02 : 0|8@1+ (1,0) [0|255] ""  IMM
 SG_ M2I_Byrack_HVS_IMM15_02 : 8|16@1+ (0.1,0) [0|6553.5] "v"  IMM
 SG_ M2I_Byrack_Enable_IMM15_02 : 24|2@1+ (1,0) [0|3] ""  IMM
 SG_ M2I_Byrack_ReVeEnable_IMM15_02 : 26|2@1+ (1,0) [0|3] ""  IMM
 SG_ Reserved_02 : 28|4@1+ (1,0) [0|15] ""  IMM
 SG_ M2I_Byrack_IsPostTm_IMM15_02 : 32|8@1+ (0.01,0) [0|2.55] "s"  IMM
 SG_ M2I_Byrack_SysABStTm_IMM15_02 : 40|16@1+ (0.01,0) [0|655.35] "s"  IMM
 SG_ Reserved_02 : 56|8@1+ (1,0) [0|255] ""  IMM

BO_ 2332110739 M2I_Byrack_SUMDATA15__03: 8 MBMU
 SG_ CRC_M2I_Byrack_IMM15_03 : 0|8@1+ (1,0) [0|255] ""  IMM
 SG_ M2I_Byrack_HVS_IMM15_03 : 8|16@1+ (0.1,0) [0|6553.5] "v"  IMM
 SG_ M2I_Byrack_Enable_IMM15_03 : 24|2@1+ (1,0) [0|3] ""  IMM
 SG_ M2I_Byrack_ReVeEnable_IMM15_03 : 26|2@1+ (1,0) [0|3] ""  IMM
 SG_ Reserved_03 : 28|4@1+ (1,0) [0|15] ""  IMM
 SG_ M2I_Byrack_IsPostTm_IMM15_03 : 32|8@1+ (0.01,0) [0|2.55] "s"  IMM
 SG_ M2I_Byrack_SysABStTm_IMM15_03 : 40|16@1+ (0.01,0) [0|655.35] "s"  IMM
 SG_ Reserved_03 : 56|8@1+ (1,0) [0|255] ""  IMM

BO_ 2332110740 M2I_Byrack_SUMDATA15__04: 8 MBMU
 SG_ CRC_M2I_Byrack_IMM15_04 : 0|8@1+ (1,0) [0|255] ""  IMM
 SG_ M2I_Byrack_HVS_IMM15_04 : 8|16@1+ (0.1,0) [0|6553.5] "v"  IMM
 SG_ M2I_Byrack_Enable_IMM15_04 : 24|2@1+ (1,0) [0|3] ""  IMM
 SG_ M2I_Byrack_ReVeEnable_IMM15_04 : 26|2@1+ (1,0) [0|3] ""  IMM
 SG_ Reserved_04 : 28|4@1+ (1,0) [0|15] ""  IMM
 SG_ M2I_Byrack_IsPostTm_IMM15_04 : 32|8@1+ (0.01,0) [0|2.55] "s"  IMM
 SG_ M2I_Byrack_SysABStTm_IMM15_04 : 40|16@1+ (0.01,0) [0|655.35] "s"  IMM
 SG_ Reserved_04 : 56|8@1+ (1,0) [0|255] ""  IMM

BO_ 2332110741 M2I_Byrack_SUMDATA15__05: 8 MBMU
 SG_ CRC_M2I_Byrack_IMM15_05 : 0|8@1+ (1,0) [0|255] ""  IMM
 SG_ M2I_Byrack_HVS_IMM15_05 : 8|16@1+ (0.1,0) [0|6553.5] "v"  IMM
 SG_ M2I_Byrack_Enable_IMM15_05 : 24|2@1+ (1,0) [0|3] ""  IMM
 SG_ M2I_Byrack_ReVeEnable_IMM15_05 : 26|2@1+ (1,0) [0|3] ""  IMM
 SG_ Reserved_05 : 28|4@1+ (1,0) [0|15] ""  IMM
 SG_ M2I_Byrack_IsPostTm_IMM15_05 : 32|8@1+ (0.01,0) [0|2.55] "s"  IMM
 SG_ M2I_Byrack_SysABStTm_IMM15_05 : 40|16@1+ (0.01,0) [0|655.35] "s"  IMM
 SG_ Reserved_05 : 56|8@1+ (1,0) [0|255] ""  IMM

BO_ 2332110742 M2I_Byrack_SUMDATA15__06: 8 MBMU
 SG_ CRC_M2I_Byrack_IMM15_06 : 0|8@1+ (1,0) [0|255] ""  IMM
 SG_ M2I_Byrack_HVS_IMM15_06 : 8|16@1+ (0.1,0) [0|6553.5] "v"  IMM
 SG_ M2I_Byrack_Enable_IMM15_06 : 24|2@1+ (1,0) [0|3] ""  IMM
 SG_ M2I_Byrack_ReVeEnable_IMM15_06 : 26|2@1+ (1,0) [0|3] ""  IMM
 SG_ Reserved_06 : 28|4@1+ (1,0) [0|15] ""  IMM
 SG_ M2I_Byrack_IsPostTm_IMM15_06 : 32|8@1+ (0.01,0) [0|2.55] "s"  IMM
 SG_ M2I_Byrack_SysABStTm_IMM15_06 : 40|16@1+ (0.01,0) [0|655.35] "s"  IMM
 SG_ Reserved_06 : 56|8@1+ (1,0) [0|255] ""  IMM

BO_ 2332110743 M2I_Byrack_SUMDATA15__07: 8 MBMU
 SG_ CRC_M2I_Byrack_IMM15_07 : 0|8@1+ (1,0) [0|255] ""  IMM
 SG_ M2I_Byrack_HVS_IMM15_07 : 8|16@1+ (0.1,0) [0|6553.5] "v"  IMM
 SG_ M2I_Byrack_Enable_IMM15_07 : 24|2@1+ (1,0) [0|3] ""  IMM
 SG_ M2I_Byrack_ReVeEnable_IMM15_07 : 26|2@1+ (1,0) [0|3] ""  IMM
 SG_ Reserved_07 : 28|4@1+ (1,0) [0|15] ""  IMM
 SG_ M2I_Byrack_IsPostTm_IMM15_07 : 32|8@1+ (0.01,0) [0|2.55] "s"  IMM
 SG_ M2I_Byrack_SysABStTm_IMM15_07 : 40|16@1+ (0.01,0) [0|655.35] "s"  IMM
 SG_ Reserved_07 : 56|8@1+ (1,0) [0|255] ""  IMM

BO_ 2332110744 M2I_Byrack_SUMDATA15__08: 8 MBMU
 SG_ CRC_M2I_Byrack_IMM15_08 : 0|8@1+ (1,0) [0|255] ""  IMM
 SG_ M2I_Byrack_HVS_IMM15_08 : 8|16@1+ (0.1,0) [0|6553.5] "v"  IMM
 SG_ M2I_Byrack_Enable_IMM15_08 : 24|2@1+ (1,0) [0|3] ""  IMM
 SG_ M2I_Byrack_ReVeEnable_IMM15_08 : 26|2@1+ (1,0) [0|3] ""  IMM
 SG_ Reserved_08 : 28|4@1+ (1,0) [0|15] ""  IMM
 SG_ M2I_Byrack_IsPostTm_IMM15_08 : 32|8@1+ (0.01,0) [0|2.55] "s"  IMM
 SG_ M2I_Byrack_SysABStTm_IMM15_08 : 40|16@1+ (0.01,0) [0|655.35] "s"  IMM
 SG_ Reserved_08 : 56|8@1+ (1,0) [0|255] ""  IMM

BO_ 2332110745 M2I_Byrack_SUMDATA15__09: 8 MBMU
 SG_ CRC_M2I_Byrack_IMM15_09 : 0|8@1+ (1,0) [0|255] ""  IMM
 SG_ M2I_Byrack_HVS_IMM15_09 : 8|16@1+ (0.1,0) [0|6553.5] "v"  IMM
 SG_ M2I_Byrack_Enable_IMM15_09 : 24|2@1+ (1,0) [0|3] ""  IMM
 SG_ M2I_Byrack_ReVeEnable_IMM15_09 : 26|2@1+ (1,0) [0|3] ""  IMM
 SG_ Reserved_09 : 28|4@1+ (1,0) [0|15] ""  IMM
 SG_ M2I_Byrack_IsPostTm_IMM15_09 : 32|8@1+ (0.01,0) [0|2.55] "s"  IMM
 SG_ M2I_Byrack_SysABStTm_IMM15_09 : 40|16@1+ (0.01,0) [0|655.35] "s"  IMM
 SG_ Reserved_09 : 56|8@1+ (1,0) [0|255] ""  IMM

BO_ 2332110746 M2I_Byrack_SUMDATA15__10: 8 MBMU
 SG_ CRC_M2I_Byrack_IMM15_10 : 0|8@1+ (1,0) [0|255] ""  IMM
 SG_ M2I_Byrack_HVS_IMM15_10 : 8|16@1+ (0.1,0) [0|6553.5] "v"  IMM
 SG_ M2I_Byrack_Enable_IMM15_10 : 24|2@1+ (1,0) [0|3] ""  IMM
 SG_ M2I_Byrack_ReVeEnable_IMM15_10 : 26|2@1+ (1,0) [0|3] ""  IMM
 SG_ Reserved_10 : 28|4@1+ (1,0) [0|15] ""  IMM
 SG_ M2I_Byrack_IsPostTm_IMM15_10 : 32|8@1+ (0.01,0) [0|2.55] "s"  IMM
 SG_ M2I_Byrack_SysABStTm_IMM15_10 : 40|16@1+ (0.01,0) [0|655.35] "s"  IMM
 SG_ Reserved_10 : 56|8@1+ (1,0) [0|255] ""  IMM

BO_ 2332110747 M2I_Byrack_SUMDATA15__11: 8 MBMU
 SG_ CRC_M2I_Byrack_IMM15_11 : 0|8@1+ (1,0) [0|255] ""  IMM
 SG_ M2I_Byrack_HVS_IMM15_11 : 8|16@1+ (0.1,0) [0|6553.5] "v"  IMM
 SG_ M2I_Byrack_Enable_IMM15_11 : 24|2@1+ (1,0) [0|3] ""  IMM
 SG_ M2I_Byrack_ReVeEnable_IMM15_11 : 26|2@1+ (1,0) [0|3] ""  IMM
 SG_ Reserved_11 : 28|4@1+ (1,0) [0|15] ""  IMM
 SG_ M2I_Byrack_IsPostTm_IMM15_11 : 32|8@1+ (0.01,0) [0|2.55] "s"  IMM
 SG_ M2I_Byrack_SysABStTm_IMM15_11 : 40|16@1+ (0.01,0) [0|655.35] "s"  IMM
 SG_ Reserved_11 : 56|8@1+ (1,0) [0|255] ""  IMM

BO_ 2332110748 M2I_Byrack_SUMDATA15__12: 8 MBMU
 SG_ CRC_M2I_Byrack_IMM15_12 : 0|8@1+ (1,0) [0|255] ""  IMM
 SG_ M2I_Byrack_HVS_IMM15_12 : 8|16@1+ (0.1,0) [0|6553.5] "v"  IMM
 SG_ M2I_Byrack_Enable_IMM15_12 : 24|2@1+ (1,0) [0|3] ""  IMM
 SG_ M2I_Byrack_ReVeEnable_IMM15_12 : 26|2@1+ (1,0) [0|3] ""  IMM
 SG_ Reserved_12 : 28|4@1+ (1,0) [0|15] ""  IMM
 SG_ M2I_Byrack_IsPostTm_IMM15_12 : 32|8@1+ (0.01,0) [0|2.55] "s"  IMM
 SG_ M2I_Byrack_SysABStTm_IMM15_12 : 40|16@1+ (0.01,0) [0|655.35] "s"  IMM
 SG_ Reserved_12 : 56|8@1+ (1,0) [0|255] ""  IMM

BO_ 2332110749 M2I_Byrack_SUMDATA15__13: 8 MBMU
 SG_ CRC_M2I_Byrack_IMM15_13 : 0|8@1+ (1,0) [0|255] ""  IMM
 SG_ M2I_Byrack_HVS_IMM15_13 : 8|16@1+ (0.1,0) [0|6553.5] "v"  IMM
 SG_ M2I_Byrack_Enable_IMM15_13 : 24|2@1+ (1,0) [0|3] ""  IMM
 SG_ M2I_Byrack_ReVeEnable_IMM15_13 : 26|2@1+ (1,0) [0|3] ""  IMM
 SG_ Reserved_13 : 28|4@1+ (1,0) [0|15] ""  IMM
 SG_ M2I_Byrack_IsPostTm_IMM15_13 : 32|8@1+ (0.01,0) [0|2.55] "s"  IMM
 SG_ M2I_Byrack_SysABStTm_IMM15_13 : 40|16@1+ (0.01,0) [0|655.35] "s"  IMM
 SG_ Reserved_13 : 56|8@1+ (1,0) [0|255] ""  IMM

BO_ 2332110750 M2I_Byrack_SUMDATA15__14: 8 MBMU
 SG_ CRC_M2I_Byrack_IMM15_14 : 0|8@1+ (1,0) [0|255] ""  IMM
 SG_ M2I_Byrack_HVS_IMM15_14 : 8|16@1+ (0.1,0) [0|6553.5] "v"  IMM
 SG_ M2I_Byrack_Enable_IMM15_14 : 24|2@1+ (1,0) [0|3] ""  IMM
 SG_ M2I_Byrack_ReVeEnable_IMM15_14 : 26|2@1+ (1,0) [0|3] ""  IMM
 SG_ Reserved_14 : 28|4@1+ (1,0) [0|15] ""  IMM
 SG_ M2I_Byrack_IsPostTm_IMM15_14 : 32|8@1+ (0.01,0) [0|2.55] "s"  IMM
 SG_ M2I_Byrack_SysABStTm_IMM15_14 : 40|16@1+ (0.01,0) [0|655.35] "s"  IMM
 SG_ Reserved_14 : 56|8@1+ (1,0) [0|255] ""  IMM

BO_ 2332110751 M2I_Byrack_SUMDATA15__15: 8 MBMU
 SG_ CRC_M2I_Byrack_IMM15_15 : 0|8@1+ (1,0) [0|255] ""  IMM
 SG_ M2I_Byrack_HVS_IMM15_15 : 8|16@1+ (0.1,0) [0|6553.5] "v"  IMM
 SG_ M2I_Byrack_Enable_IMM15_15 : 24|2@1+ (1,0) [0|3] ""  IMM
 SG_ M2I_Byrack_ReVeEnable_IMM15_15 : 26|2@1+ (1,0) [0|3] ""  IMM
 SG_ Reserved_15 : 28|4@1+ (1,0) [0|15] ""  IMM
 SG_ M2I_Byrack_IsPostTm_IMM15_15 : 32|8@1+ (0.01,0) [0|2.55] "s"  IMM
 SG_ M2I_Byrack_SysABStTm_IMM15_15 : 40|16@1+ (0.01,0) [0|655.35] "s"  IMM
 SG_ Reserved_15 : 56|8@1+ (1,0) [0|255] ""  IMM

BO_ 2332110752 M2I_Byrack_SUMDATA15__16: 8 MBMU
 SG_ CRC_M2I_Byrack_IMM15_16 : 0|8@1+ (1,0) [0|255] ""  IMM
 SG_ M2I_Byrack_HVS_IMM15_16 : 8|16@1+ (0.1,0) [0|6553.5] "v"  IMM
 SG_ M2I_Byrack_Enable_IMM15_16 : 24|2@1+ (1,0) [0|3] ""  IMM
 SG_ M2I_Byrack_ReVeEnable_IMM15_16 : 26|2@1+ (1,0) [0|3] ""  IMM
 SG_ Reserved_16 : 28|4@1+ (1,0) [0|15] ""  IMM
 SG_ M2I_Byrack_IsPostTm_IMM15_16 : 32|8@1+ (0.01,0) [0|2.55] "s"  IMM
 SG_ M2I_Byrack_SysABStTm_IMM15_16 : 40|16@1+ (0.01,0) [0|655.35] "s"  IMM
 SG_ Reserved_16 : 56|8@1+ (1,0) [0|255] ""  IMM

BO_ 2332110753 M2I_Byrack_SUMDATA15__17: 8 MBMU
 SG_ CRC_M2I_Byrack_IMM15_17 : 0|8@1+ (1,0) [0|255] ""  IMM
 SG_ M2I_Byrack_HVS_IMM15_17 : 8|16@1+ (0.1,0) [0|6553.5] "v"  IMM
 SG_ M2I_Byrack_Enable_IMM15_17 : 24|2@1+ (1,0) [0|3] ""  IMM
 SG_ M2I_Byrack_ReVeEnable_IMM15_17 : 26|2@1+ (1,0) [0|3] ""  IMM
 SG_ Reserved_17 : 28|4@1+ (1,0) [0|15] ""  IMM
 SG_ M2I_Byrack_IsPostTm_IMM15_17 : 32|8@1+ (0.01,0) [0|2.55] "s"  IMM
 SG_ M2I_Byrack_SysABStTm_IMM15_17 : 40|16@1+ (0.01,0) [0|655.35] "s"  IMM
 SG_ Reserved_17 : 56|8@1+ (1,0) [0|255] ""  IMM

BO_ 2332110754 M2I_Byrack_SUMDATA15__18: 8 MBMU
 SG_ CRC_M2I_Byrack_IMM15_18 : 0|8@1+ (1,0) [0|255] ""  IMM
 SG_ M2I_Byrack_HVS_IMM15_18 : 8|16@1+ (0.1,0) [0|6553.5] "v"  IMM
 SG_ M2I_Byrack_Enable_IMM15_18 : 24|2@1+ (1,0) [0|3] ""  IMM
 SG_ M2I_Byrack_ReVeEnable_IMM15_18 : 26|2@1+ (1,0) [0|3] ""  IMM
 SG_ Reserved_18 : 28|4@1+ (1,0) [0|15] ""  IMM
 SG_ M2I_Byrack_IsPostTm_IMM15_18 : 32|8@1+ (0.01,0) [0|2.55] "s"  IMM
 SG_ M2I_Byrack_SysABStTm_IMM15_18 : 40|16@1+ (0.01,0) [0|655.35] "s"  IMM
 SG_ Reserved_18 : 56|8@1+ (1,0) [0|255] ""  IMM

BO_ 2332110755 M2I_Byrack_SUMDATA15__19: 8 MBMU
 SG_ CRC_M2I_Byrack_IMM15_19 : 0|8@1+ (1,0) [0|255] ""  IMM
 SG_ M2I_Byrack_HVS_IMM15_19 : 8|16@1+ (0.1,0) [0|6553.5] "v"  IMM
 SG_ M2I_Byrack_Enable_IMM15_19 : 24|2@1+ (1,0) [0|3] ""  IMM
 SG_ M2I_Byrack_ReVeEnable_IMM15_19 : 26|2@1+ (1,0) [0|3] ""  IMM
 SG_ Reserved_19 : 28|4@1+ (1,0) [0|15] ""  IMM
 SG_ M2I_Byrack_IsPostTm_IMM15_19 : 32|8@1+ (0.01,0) [0|2.55] "s"  IMM
 SG_ M2I_Byrack_SysABStTm_IMM15_19 : 40|16@1+ (0.01,0) [0|655.35] "s"  IMM
 SG_ Reserved_19 : 56|8@1+ (1,0) [0|255] ""  IMM

BO_ 2332110756 M2I_Byrack_SUMDATA15__20: 8 MBMU
 SG_ CRC_M2I_Byrack_IMM15_20 : 0|8@1+ (1,0) [0|255] ""  IMM
 SG_ M2I_Byrack_HVS_IMM15_20 : 8|16@1+ (0.1,0) [0|6553.5] "v"  IMM
 SG_ M2I_Byrack_Enable_IMM15_20 : 24|2@1+ (1,0) [0|3] ""  IMM
 SG_ M2I_Byrack_ReVeEnable_IMM15_20 : 26|2@1+ (1,0) [0|3] ""  IMM
 SG_ Reserved_20 : 28|4@1+ (1,0) [0|15] ""  IMM
 SG_ M2I_Byrack_IsPostTm_IMM15_20 : 32|8@1+ (0.01,0) [0|2.55] "s"  IMM
 SG_ M2I_Byrack_SysABStTm_IMM15_20 : 40|16@1+ (0.01,0) [0|655.35] "s"  IMM
 SG_ Reserved_20 : 56|8@1+ (1,0) [0|255] ""  IMM

BO_ 2332110757 M2I_Byrack_SUMDATA15__21: 8 MBMU
 SG_ CRC_M2I_Byrack_IMM15_21 : 0|8@1+ (1,0) [0|255] ""  IMM
 SG_ M2I_Byrack_HVS_IMM15_21 : 8|16@1+ (0.1,0) [0|6553.5] "v"  IMM
 SG_ M2I_Byrack_Enable_IMM15_21 : 24|2@1+ (1,0) [0|3] ""  IMM
 SG_ M2I_Byrack_ReVeEnable_IMM15_21 : 26|2@1+ (1,0) [0|3] ""  IMM
 SG_ Reserved_21 : 28|4@1+ (1,0) [0|15] ""  IMM
 SG_ M2I_Byrack_IsPostTm_IMM15_21 : 32|8@1+ (0.01,0) [0|2.55] "s"  IMM
 SG_ M2I_Byrack_SysABStTm_IMM15_21 : 40|16@1+ (0.01,0) [0|655.35] "s"  IMM
 SG_ Reserved_21 : 56|8@1+ (1,0) [0|255] ""  IMM

BO_ 2332110758 M2I_Byrack_SUMDATA15__22: 8 MBMU
 SG_ CRC_M2I_Byrack_IMM15_22 : 0|8@1+ (1,0) [0|255] ""  IMM
 SG_ M2I_Byrack_HVS_IMM15_22 : 8|16@1+ (0.1,0) [0|6553.5] "v"  IMM
 SG_ M2I_Byrack_Enable_IMM15_22 : 24|2@1+ (1,0) [0|3] ""  IMM
 SG_ M2I_Byrack_ReVeEnable_IMM15_22 : 26|2@1+ (1,0) [0|3] ""  IMM
 SG_ Reserved_22 : 28|4@1+ (1,0) [0|15] ""  IMM
 SG_ M2I_Byrack_IsPostTm_IMM15_22 : 32|8@1+ (0.01,0) [0|2.55] "s"  IMM
 SG_ M2I_Byrack_SysABStTm_IMM15_22 : 40|16@1+ (0.01,0) [0|655.35] "s"  IMM
 SG_ Reserved_22 : 56|8@1+ (1,0) [0|255] ""  IMM

BO_ 2332110759 M2I_Byrack_SUMDATA15__23: 8 MBMU
 SG_ CRC_M2I_Byrack_IMM15_23 : 0|8@1+ (1,0) [0|255] ""  IMM
 SG_ M2I_Byrack_HVS_IMM15_23 : 8|16@1+ (0.1,0) [0|6553.5] "v"  IMM
 SG_ M2I_Byrack_Enable_IMM15_23 : 24|2@1+ (1,0) [0|3] ""  IMM
 SG_ M2I_Byrack_ReVeEnable_IMM15_23 : 26|2@1+ (1,0) [0|3] ""  IMM
 SG_ Reserved_23 : 28|4@1+ (1,0) [0|15] ""  IMM
 SG_ M2I_Byrack_IsPostTm_IMM15_23 : 32|8@1+ (0.01,0) [0|2.55] "s"  IMM
 SG_ M2I_Byrack_SysABStTm_IMM15_23 : 40|16@1+ (0.01,0) [0|655.35] "s"  IMM
 SG_ Reserved_23 : 56|8@1+ (1,0) [0|255] ""  IMM

BO_ 2332110760 M2I_Byrack_SUMDATA15__24: 8 MBMU
 SG_ CRC_M2I_Byrack_IMM15_24 : 0|8@1+ (1,0) [0|255] ""  IMM
 SG_ M2I_Byrack_HVS_IMM15_24 : 8|16@1+ (0.1,0) [0|6553.5] "v"  IMM
 SG_ M2I_Byrack_Enable_IMM15_24 : 24|2@1+ (1,0) [0|3] ""  IMM
 SG_ M2I_Byrack_ReVeEnable_IMM15_24 : 26|2@1+ (1,0) [0|3] ""  IMM
 SG_ Reserved_24 : 28|4@1+ (1,0) [0|15] ""  IMM
 SG_ M2I_Byrack_IsPostTm_IMM15_24 : 32|8@1+ (0.01,0) [0|2.55] "s"  IMM
 SG_ M2I_Byrack_SysABStTm_IMM15_24 : 40|16@1+ (0.01,0) [0|655.35] "s"  IMM
 SG_ Reserved_24 : 56|8@1+ (1,0) [0|255] ""  IMM

BO_ 2332110761 M2I_Byrack_SUMDATA15__25: 8 MBMU
 SG_ CRC_M2I_Byrack_IMM15_25 : 0|8@1+ (1,0) [0|255] ""  IMM
 SG_ M2I_Byrack_HVS_IMM15_25 : 8|16@1+ (0.1,0) [0|6553.5] "v"  IMM
 SG_ M2I_Byrack_Enable_IMM15_25 : 24|2@1+ (1,0) [0|3] ""  IMM
 SG_ M2I_Byrack_ReVeEnable_IMM15_25 : 26|2@1+ (1,0) [0|3] ""  IMM
 SG_ Reserved_25 : 28|4@1+ (1,0) [0|15] ""  IMM
 SG_ M2I_Byrack_IsPostTm_IMM15_25 : 32|8@1+ (0.01,0) [0|2.55] "s"  IMM
 SG_ M2I_Byrack_SysABStTm_IMM15_25 : 40|16@1+ (0.01,0) [0|655.35] "s"  IMM
 SG_ Reserved_25 : 56|8@1+ (1,0) [0|255] ""  IMM

BO_ 2332110762 M2I_Byrack_SUMDATA15__26: 8 MBMU
 SG_ CRC_M2I_Byrack_IMM15_26 : 0|8@1+ (1,0) [0|255] ""  IMM
 SG_ M2I_Byrack_HVS_IMM15_26 : 8|16@1+ (0.1,0) [0|6553.5] "v"  IMM
 SG_ M2I_Byrack_Enable_IMM15_26 : 24|2@1+ (1,0) [0|3] ""  IMM
 SG_ M2I_Byrack_ReVeEnable_IMM15_26 : 26|2@1+ (1,0) [0|3] ""  IMM
 SG_ Reserved_26 : 28|4@1+ (1,0) [0|15] ""  IMM
 SG_ M2I_Byrack_IsPostTm_IMM15_26 : 32|8@1+ (0.01,0) [0|2.55] "s"  IMM
 SG_ M2I_Byrack_SysABStTm_IMM15_26 : 40|16@1+ (0.01,0) [0|655.35] "s"  IMM
 SG_ Reserved_26 : 56|8@1+ (1,0) [0|255] ""  IMM

BO_ 2332110763 M2I_Byrack_SUMDATA15__27: 8 MBMU
 SG_ CRC_M2I_Byrack_IMM15_27 : 0|8@1+ (1,0) [0|255] ""  IMM
 SG_ M2I_Byrack_HVS_IMM15_27 : 8|16@1+ (0.1,0) [0|6553.5] "v"  IMM
 SG_ M2I_Byrack_Enable_IMM15_27 : 24|2@1+ (1,0) [0|3] ""  IMM
 SG_ M2I_Byrack_ReVeEnable_IMM15_27 : 26|2@1+ (1,0) [0|3] ""  IMM
 SG_ Reserved_27 : 28|4@1+ (1,0) [0|15] ""  IMM
 SG_ M2I_Byrack_IsPostTm_IMM15_27 : 32|8@1+ (0.01,0) [0|2.55] "s"  IMM
 SG_ M2I_Byrack_SysABStTm_IMM15_27 : 40|16@1+ (0.01,0) [0|655.35] "s"  IMM
 SG_ Reserved_27 : 56|8@1+ (1,0) [0|255] ""  IMM

BO_ 2332110764 M2I_Byrack_SUMDATA15__28: 8 MBMU
 SG_ CRC_M2I_Byrack_IMM15_28 : 0|8@1+ (1,0) [0|255] ""  IMM
 SG_ M2I_Byrack_HVS_IMM15_28 : 8|16@1+ (0.1,0) [0|6553.5] "v"  IMM
 SG_ M2I_Byrack_Enable_IMM15_28 : 24|2@1+ (1,0) [0|3] ""  IMM
 SG_ M2I_Byrack_ReVeEnable_IMM15_28 : 26|2@1+ (1,0) [0|3] ""  IMM
 SG_ Reserved_28 : 28|4@1+ (1,0) [0|15] ""  IMM
 SG_ M2I_Byrack_IsPostTm_IMM15_28 : 32|8@1+ (0.01,0) [0|2.55] "s"  IMM
 SG_ M2I_Byrack_SysABStTm_IMM15_28 : 40|16@1+ (0.01,0) [0|655.35] "s"  IMM
 SG_ Reserved_28 : 56|8@1+ (1,0) [0|255] ""  IMM

BO_ 2332110765 M2I_Byrack_SUMDATA15__29: 8 MBMU
 SG_ CRC_M2I_Byrack_IMM15_29 : 0|8@1+ (1,0) [0|255] ""  IMM
 SG_ M2I_Byrack_HVS_IMM15_29 : 8|16@1+ (0.1,0) [0|6553.5] "v"  IMM
 SG_ M2I_Byrack_Enable_IMM15_29 : 24|2@1+ (1,0) [0|3] ""  IMM
 SG_ M2I_Byrack_ReVeEnable_IMM15_29 : 26|2@1+ (1,0) [0|3] ""  IMM
 SG_ Reserved_29 : 28|4@1+ (1,0) [0|15] ""  IMM
 SG_ M2I_Byrack_IsPostTm_IMM15_29 : 32|8@1+ (0.01,0) [0|2.55] "s"  IMM
 SG_ M2I_Byrack_SysABStTm_IMM15_29 : 40|16@1+ (0.01,0) [0|655.35] "s"  IMM
 SG_ Reserved_29 : 56|8@1+ (1,0) [0|255] ""  IMM

BO_ 2332110766 M2I_Byrack_SUMDATA15__30: 8 MBMU
 SG_ CRC_M2I_Byrack_IMM15_30 : 0|8@1+ (1,0) [0|255] ""  IMM
 SG_ M2I_Byrack_HVS_IMM15_30 : 8|16@1+ (0.1,0) [0|6553.5] "v"  IMM
 SG_ M2I_Byrack_Enable_IMM15_30 : 24|2@1+ (1,0) [0|3] ""  IMM
 SG_ M2I_Byrack_ReVeEnable_IMM15_30 : 26|2@1+ (1,0) [0|3] ""  IMM
 SG_ Reserved_30 : 28|4@1+ (1,0) [0|15] ""  IMM
 SG_ M2I_Byrack_IsPostTm_IMM15_30 : 32|8@1+ (0.01,0) [0|2.55] "s"  IMM
 SG_ M2I_Byrack_SysABStTm_IMM15_30 : 40|16@1+ (0.01,0) [0|655.35] "s"  IMM
 SG_ Reserved_30 : 56|8@1+ (1,0) [0|255] ""  IMM

BO_ 2332110767 M2I_Byrack_SUMDATA15__31: 8 MBMU
 SG_ CRC_M2I_Byrack_IMM15_31 : 0|8@1+ (1,0) [0|255] ""  IMM
 SG_ M2I_Byrack_HVS_IMM15_31 : 8|16@1+ (0.1,0) [0|6553.5] "v"  IMM
 SG_ M2I_Byrack_Enable_IMM15_31 : 24|2@1+ (1,0) [0|3] ""  IMM
 SG_ M2I_Byrack_ReVeEnable_IMM15_31 : 26|2@1+ (1,0) [0|3] ""  IMM
 SG_ Reserved_31 : 28|4@1+ (1,0) [0|15] ""  IMM
 SG_ M2I_Byrack_IsPostTm_IMM15_31 : 32|8@1+ (0.01,0) [0|2.55] "s"  IMM
 SG_ M2I_Byrack_SysABStTm_IMM15_31 : 40|16@1+ (0.01,0) [0|655.35] "s"  IMM
 SG_ Reserved_31 : 56|8@1+ (1,0) [0|255] ""  IMM

BO_ 2332110993 M2I_Byrack_SUMDATA16__01: 8 MBMU
 SG_ CRC_M2I_Byrack_IMM16_01 : 0|8@1+ (1,0) [0|255] ""  IMM
 SG_ M2I_Byrack_HVS_IMM16_01 : 8|16@1+ (0.1,0) [0|6553.5] "v"  IMM
 SG_ M2I_Byrack_Enable_IMM16_01 : 24|2@1+ (1,0) [0|3] ""  IMM
 SG_ M2I_Byrack_ReVeEnable_IMM16_01 : 26|2@1+ (1,0) [0|3] ""  IMM
 SG_ Reserved_01 : 28|4@1+ (1,0) [0|15] ""  IMM
 SG_ M2I_Byrack_IsPostTm_IMM16_01 : 32|8@1+ (0.01,0) [0|2.55] "s"  IMM
 SG_ M2I_Byrack_SysABStTm_IMM16_01 : 40|16@1+ (0.01,0) [0|655.35] "s"  IMM
 SG_ Reserved_01 : 56|8@1+ (1,0) [0|255] ""  IMM

BO_ 2332110994 M2I_Byrack_SUMDATA16__02: 8 MBMU
 SG_ CRC_M2I_Byrack_IMM16_02 : 0|8@1+ (1,0) [0|255] ""  IMM
 SG_ M2I_Byrack_HVS_IMM16_02 : 8|16@1+ (0.1,0) [0|6553.5] "v"  IMM
 SG_ M2I_Byrack_Enable_IMM16_02 : 24|2@1+ (1,0) [0|3] ""  IMM
 SG_ M2I_Byrack_ReVeEnable_IMM16_02 : 26|2@1+ (1,0) [0|3] ""  IMM
 SG_ Reserved_02 : 28|4@1+ (1,0) [0|15] ""  IMM
 SG_ M2I_Byrack_IsPostTm_IMM16_02 : 32|8@1+ (0.01,0) [0|2.55] "s"  IMM
 SG_ M2I_Byrack_SysABStTm_IMM16_02 : 40|16@1+ (0.01,0) [0|655.35] "s"  IMM
 SG_ Reserved_02 : 56|8@1+ (1,0) [0|255] ""  IMM

BO_ 2332110995 M2I_Byrack_SUMDATA16__03: 8 MBMU
 SG_ CRC_M2I_Byrack_IMM16_03 : 0|8@1+ (1,0) [0|255] ""  IMM
 SG_ M2I_Byrack_HVS_IMM16_03 : 8|16@1+ (0.1,0) [0|6553.5] "v"  IMM
 SG_ M2I_Byrack_Enable_IMM16_03 : 24|2@1+ (1,0) [0|3] ""  IMM
 SG_ M2I_Byrack_ReVeEnable_IMM16_03 : 26|2@1+ (1,0) [0|3] ""  IMM
 SG_ Reserved_03 : 28|4@1+ (1,0) [0|15] ""  IMM
 SG_ M2I_Byrack_IsPostTm_IMM16_03 : 32|8@1+ (0.01,0) [0|2.55] "s"  IMM
 SG_ M2I_Byrack_SysABStTm_IMM16_03 : 40|16@1+ (0.01,0) [0|655.35] "s"  IMM
 SG_ Reserved_03 : 56|8@1+ (1,0) [0|255] ""  IMM

BO_ 2332110996 M2I_Byrack_SUMDATA16__04: 8 MBMU
 SG_ CRC_M2I_Byrack_IMM16_04 : 0|8@1+ (1,0) [0|255] ""  IMM
 SG_ M2I_Byrack_HVS_IMM16_04 : 8|16@1+ (0.1,0) [0|6553.5] "v"  IMM
 SG_ M2I_Byrack_Enable_IMM16_04 : 24|2@1+ (1,0) [0|3] ""  IMM
 SG_ M2I_Byrack_ReVeEnable_IMM16_04 : 26|2@1+ (1,0) [0|3] ""  IMM
 SG_ Reserved_04 : 28|4@1+ (1,0) [0|15] ""  IMM
 SG_ M2I_Byrack_IsPostTm_IMM16_04 : 32|8@1+ (0.01,0) [0|2.55] "s"  IMM
 SG_ M2I_Byrack_SysABStTm_IMM16_04 : 40|16@1+ (0.01,0) [0|655.35] "s"  IMM
 SG_ Reserved_04 : 56|8@1+ (1,0) [0|255] ""  IMM

BO_ 2332110997 M2I_Byrack_SUMDATA16__05: 8 MBMU
 SG_ CRC_M2I_Byrack_IMM16_05 : 0|8@1+ (1,0) [0|255] ""  IMM
 SG_ M2I_Byrack_HVS_IMM16_05 : 8|16@1+ (0.1,0) [0|6553.5] "v"  IMM
 SG_ M2I_Byrack_Enable_IMM16_05 : 24|2@1+ (1,0) [0|3] ""  IMM
 SG_ M2I_Byrack_ReVeEnable_IMM16_05 : 26|2@1+ (1,0) [0|3] ""  IMM
 SG_ Reserved_05 : 28|4@1+ (1,0) [0|15] ""  IMM
 SG_ M2I_Byrack_IsPostTm_IMM16_05 : 32|8@1+ (0.01,0) [0|2.55] "s"  IMM
 SG_ M2I_Byrack_SysABStTm_IMM16_05 : 40|16@1+ (0.01,0) [0|655.35] "s"  IMM
 SG_ Reserved_05 : 56|8@1+ (1,0) [0|255] ""  IMM

BO_ 2332110998 M2I_Byrack_SUMDATA16__06: 8 MBMU
 SG_ CRC_M2I_Byrack_IMM16_06 : 0|8@1+ (1,0) [0|255] ""  IMM
 SG_ M2I_Byrack_HVS_IMM16_06 : 8|16@1+ (0.1,0) [0|6553.5] "v"  IMM
 SG_ M2I_Byrack_Enable_IMM16_06 : 24|2@1+ (1,0) [0|3] ""  IMM
 SG_ M2I_Byrack_ReVeEnable_IMM16_06 : 26|2@1+ (1,0) [0|3] ""  IMM
 SG_ Reserved_06 : 28|4@1+ (1,0) [0|15] ""  IMM
 SG_ M2I_Byrack_IsPostTm_IMM16_06 : 32|8@1+ (0.01,0) [0|2.55] "s"  IMM
 SG_ M2I_Byrack_SysABStTm_IMM16_06 : 40|16@1+ (0.01,0) [0|655.35] "s"  IMM
 SG_ Reserved_06 : 56|8@1+ (1,0) [0|255] ""  IMM

CM_ SG_ 2332109484 CRC_M2I_Byrack_IMM10_28 "CRC校验_IMM10";
CM_ SG_ 2332109484 M2I_Byrack_HVS_IMM10_28 "绝缘测量电压_IMM10";
CM_ SG_ 2332109484 M2I_Byrack_Enable_IMM10_28 "绝缘采样使能位_IMM10";
CM_ SG_ 2332109484 M2I_Byrack_ReVeEnable_IMM10_28 "读取软件版本使能位_IMM10";
CM_ SG_ 2332109484 Reserved_28 "预留预留";
CM_ SG_ 2332109484 M2I_Byrack_IsPostTm_IMM10_28 "绝缘采样时间_IMM10";
CM_ SG_ 2332109484 M2I_Byrack_SysABStTm_IMM10_28 "电压稳定时间_IMM10";
CM_ SG_ 2332109485 CRC_M2I_Byrack_IMM10_29 "CRC校验_IMM10";
CM_ SG_ 2332109485 M2I_Byrack_HVS_IMM10_29 "绝缘测量电压_IMM10";
CM_ SG_ 2332109485 M2I_Byrack_Enable_IMM10_29 "绝缘采样使能位_IMM10";
CM_ SG_ 2332109485 M2I_Byrack_ReVeEnable_IMM10_29 "读取软件版本使能位_IMM10";
CM_ SG_ 2332109485 Reserved_29 "预留预留";
CM_ SG_ 2332109485 M2I_Byrack_IsPostTm_IMM10_29 "绝缘采样时间_IMM10";
CM_ SG_ 2332109485 M2I_Byrack_SysABStTm_IMM10_29 "电压稳定时间_IMM10";
CM_ SG_ 2332109486 CRC_M2I_Byrack_IMM10_30 "CRC校验_IMM10";
CM_ SG_ 2332109486 M2I_Byrack_HVS_IMM10_30 "绝缘测量电压_IMM10";
CM_ SG_ 2332109486 M2I_Byrack_Enable_IMM10_30 "绝缘采样使能位_IMM10";
CM_ SG_ 2332109486 M2I_Byrack_ReVeEnable_IMM10_30 "读取软件版本使能位_IMM10";
CM_ SG_ 2332109486 Reserved_30 "预留预留";
CM_ SG_ 2332109486 M2I_Byrack_IsPostTm_IMM10_30 "绝缘采样时间_IMM10";
CM_ SG_ 2332109486 M2I_Byrack_SysABStTm_IMM10_30 "电压稳定时间_IMM10";
CM_ SG_ 2332109487 CRC_M2I_Byrack_IMM10_31 "CRC校验_IMM10";
CM_ SG_ 2332109487 M2I_Byrack_HVS_IMM10_31 "绝缘测量电压_IMM10";
CM_ SG_ 2332109487 M2I_Byrack_Enable_IMM10_31 "绝缘采样使能位_IMM10";
CM_ SG_ 2332109487 M2I_Byrack_ReVeEnable_IMM10_31 "读取软件版本使能位_IMM10";
CM_ SG_ 2332109487 Reserved_31 "预留预留";
CM_ SG_ 2332109487 M2I_Byrack_IsPostTm_IMM10_31 "绝缘采样时间_IMM10";
CM_ SG_ 2332109487 M2I_Byrack_SysABStTm_IMM10_31 "电压稳定时间_IMM10";
CM_ SG_ 2332109713 CRC_M2I_Byrack_IMM11_01 "CRC校验_IMM11";
CM_ SG_ 2332109713 M2I_Byrack_HVS_IMM11_01 "绝缘测量电压_IMM11";
CM_ SG_ 2332109713 M2I_Byrack_Enable_IMM11_01 "绝缘采样使能位_IMM11";
CM_ SG_ 2332109713 M2I_Byrack_ReVeEnable_IMM11_01 "读取软件版本使能位_IMM11";
CM_ SG_ 2332109713 Reserved_01 "预留预留";
CM_ SG_ 2332109713 M2I_Byrack_IsPostTm_IMM11_01 "绝缘采样时间_IMM11";
CM_ SG_ 2332109713 M2I_Byrack_SysABStTm_IMM11_01 "电压稳定时间_IMM11";
CM_ SG_ 2332109714 CRC_M2I_Byrack_IMM11_02 "CRC校验_IMM11";
CM_ SG_ 2332109714 M2I_Byrack_HVS_IMM11_02 "绝缘测量电压_IMM11";
CM_ SG_ 2332109714 M2I_Byrack_Enable_IMM11_02 "绝缘采样使能位_IMM11";
CM_ SG_ 2332109714 M2I_Byrack_ReVeEnable_IMM11_02 "读取软件版本使能位_IMM11";
CM_ SG_ 2332109714 Reserved_02 "预留预留";
CM_ SG_ 2332109714 M2I_Byrack_IsPostTm_IMM11_02 "绝缘采样时间_IMM11";
CM_ SG_ 2332109714 M2I_Byrack_SysABStTm_IMM11_02 "电压稳定时间_IMM11";
CM_ SG_ 2332109715 CRC_M2I_Byrack_IMM11_03 "CRC校验_IMM11";
CM_ SG_ 2332109715 M2I_Byrack_HVS_IMM11_03 "绝缘测量电压_IMM11";
CM_ SG_ 2332109715 M2I_Byrack_Enable_IMM11_03 "绝缘采样使能位_IMM11";
CM_ SG_ 2332109715 M2I_Byrack_ReVeEnable_IMM11_03 "读取软件版本使能位_IMM11";
CM_ SG_ 2332109715 Reserved_03 "预留预留";
CM_ SG_ 2332109715 M2I_Byrack_IsPostTm_IMM11_03 "绝缘采样时间_IMM11";
CM_ SG_ 2332109715 M2I_Byrack_SysABStTm_IMM11_03 "电压稳定时间_IMM11";
CM_ SG_ 2332109716 CRC_M2I_Byrack_IMM11_04 "CRC校验_IMM11";
CM_ SG_ 2332109716 M2I_Byrack_HVS_IMM11_04 "绝缘测量电压_IMM11";
CM_ SG_ 2332109716 M2I_Byrack_Enable_IMM11_04 "绝缘采样使能位_IMM11";
CM_ SG_ 2332109716 M2I_Byrack_ReVeEnable_IMM11_04 "读取软件版本使能位_IMM11";
CM_ SG_ 2332109716 Reserved_04 "预留预留";
CM_ SG_ 2332109716 M2I_Byrack_IsPostTm_IMM11_04 "绝缘采样时间_IMM11";
CM_ SG_ 2332109716 M2I_Byrack_SysABStTm_IMM11_04 "电压稳定时间_IMM11";
CM_ SG_ 2332109717 CRC_M2I_Byrack_IMM11_05 "CRC校验_IMM11";
CM_ SG_ 2332109717 M2I_Byrack_HVS_IMM11_05 "绝缘测量电压_IMM11";
CM_ SG_ 2332109717 M2I_Byrack_Enable_IMM11_05 "绝缘采样使能位_IMM11";
CM_ SG_ 2332109717 M2I_Byrack_ReVeEnable_IMM11_05 "读取软件版本使能位_IMM11";
CM_ SG_ 2332109717 Reserved_05 "预留预留";
CM_ SG_ 2332109717 M2I_Byrack_IsPostTm_IMM11_05 "绝缘采样时间_IMM11";
CM_ SG_ 2332109717 M2I_Byrack_SysABStTm_IMM11_05 "电压稳定时间_IMM11";
CM_ SG_ 2332109718 CRC_M2I_Byrack_IMM11_06 "CRC校验_IMM11";
CM_ SG_ 2332109718 M2I_Byrack_HVS_IMM11_06 "绝缘测量电压_IMM11";
CM_ SG_ 2332109718 M2I_Byrack_Enable_IMM11_06 "绝缘采样使能位_IMM11";
CM_ SG_ 2332109718 M2I_Byrack_ReVeEnable_IMM11_06 "读取软件版本使能位_IMM11";
CM_ SG_ 2332109718 Reserved_06 "预留预留";
CM_ SG_ 2332109718 M2I_Byrack_IsPostTm_IMM11_06 "绝缘采样时间_IMM11";
CM_ SG_ 2332109718 M2I_Byrack_SysABStTm_IMM11_06 "电压稳定时间_IMM11";
CM_ SG_ 2332109719 CRC_M2I_Byrack_IMM11_07 "CRC校验_IMM11";
CM_ SG_ 2332109719 M2I_Byrack_HVS_IMM11_07 "绝缘测量电压_IMM11";
CM_ SG_ 2332109719 M2I_Byrack_Enable_IMM11_07 "绝缘采样使能位_IMM11";
CM_ SG_ 2332109719 M2I_Byrack_ReVeEnable_IMM11_07 "读取软件版本使能位_IMM11";
CM_ SG_ 2332109719 Reserved_07 "预留预留";
CM_ SG_ 2332109719 M2I_Byrack_IsPostTm_IMM11_07 "绝缘采样时间_IMM11";
CM_ SG_ 2332109719 M2I_Byrack_SysABStTm_IMM11_07 "电压稳定时间_IMM11";
CM_ SG_ 2332109720 CRC_M2I_Byrack_IMM11_08 "CRC校验_IMM11";
CM_ SG_ 2332109720 M2I_Byrack_HVS_IMM11_08 "绝缘测量电压_IMM11";
CM_ SG_ 2332109720 M2I_Byrack_Enable_IMM11_08 "绝缘采样使能位_IMM11";
CM_ SG_ 2332109720 M2I_Byrack_ReVeEnable_IMM11_08 "读取软件版本使能位_IMM11";
CM_ SG_ 2332109720 Reserved_08 "预留预留";
CM_ SG_ 2332109720 M2I_Byrack_IsPostTm_IMM11_08 "绝缘采样时间_IMM11";
CM_ SG_ 2332109720 M2I_Byrack_SysABStTm_IMM11_08 "电压稳定时间_IMM11";
CM_ SG_ 2332109721 CRC_M2I_Byrack_IMM11_09 "CRC校验_IMM11";
CM_ SG_ 2332109721 M2I_Byrack_HVS_IMM11_09 "绝缘测量电压_IMM11";
CM_ SG_ 2332109721 M2I_Byrack_Enable_IMM11_09 "绝缘采样使能位_IMM11";
CM_ SG_ 2332109721 M2I_Byrack_ReVeEnable_IMM11_09 "读取软件版本使能位_IMM11";
CM_ SG_ 2332109721 Reserved_09 "预留预留";
CM_ SG_ 2332109721 M2I_Byrack_IsPostTm_IMM11_09 "绝缘采样时间_IMM11";
CM_ SG_ 2332109721 M2I_Byrack_SysABStTm_IMM11_09 "电压稳定时间_IMM11";
CM_ SG_ 2332109722 CRC_M2I_Byrack_IMM11_10 "CRC校验_IMM11";
CM_ SG_ 2332109722 M2I_Byrack_HVS_IMM11_10 "绝缘测量电压_IMM11";
CM_ SG_ 2332109722 M2I_Byrack_Enable_IMM11_10 "绝缘采样使能位_IMM11";
CM_ SG_ 2332109722 M2I_Byrack_ReVeEnable_IMM11_10 "读取软件版本使能位_IMM11";
CM_ SG_ 2332109722 Reserved_10 "预留预留";
CM_ SG_ 2332109722 M2I_Byrack_IsPostTm_IMM11_10 "绝缘采样时间_IMM11";
CM_ SG_ 2332109722 M2I_Byrack_SysABStTm_IMM11_10 "电压稳定时间_IMM11";
CM_ SG_ 2332109723 CRC_M2I_Byrack_IMM11_11 "CRC校验_IMM11";
CM_ SG_ 2332109723 M2I_Byrack_HVS_IMM11_11 "绝缘测量电压_IMM11";
CM_ SG_ 2332109723 M2I_Byrack_Enable_IMM11_11 "绝缘采样使能位_IMM11";
CM_ SG_ 2332109723 M2I_Byrack_ReVeEnable_IMM11_11 "读取软件版本使能位_IMM11";
CM_ SG_ 2332109723 Reserved_11 "预留预留";
CM_ SG_ 2332109723 M2I_Byrack_IsPostTm_IMM11_11 "绝缘采样时间_IMM11";
CM_ SG_ 2332109723 M2I_Byrack_SysABStTm_IMM11_11 "电压稳定时间_IMM11";
CM_ SG_ 2332109724 CRC_M2I_Byrack_IMM11_12 "CRC校验_IMM11";
CM_ SG_ 2332109724 M2I_Byrack_HVS_IMM11_12 "绝缘测量电压_IMM11";
CM_ SG_ 2332109724 M2I_Byrack_Enable_IMM11_12 "绝缘采样使能位_IMM11";
CM_ SG_ 2332109724 M2I_Byrack_ReVeEnable_IMM11_12 "读取软件版本使能位_IMM11";
CM_ SG_ 2332109724 Reserved_12 "预留预留";
CM_ SG_ 2332109724 M2I_Byrack_IsPostTm_IMM11_12 "绝缘采样时间_IMM11";
CM_ SG_ 2332109724 M2I_Byrack_SysABStTm_IMM11_12 "电压稳定时间_IMM11";
CM_ SG_ 2332109725 CRC_M2I_Byrack_IMM11_13 "CRC校验_IMM11";
CM_ SG_ 2332109725 M2I_Byrack_HVS_IMM11_13 "绝缘测量电压_IMM11";
CM_ SG_ 2332109725 M2I_Byrack_Enable_IMM11_13 "绝缘采样使能位_IMM11";
CM_ SG_ 2332109725 M2I_Byrack_ReVeEnable_IMM11_13 "读取软件版本使能位_IMM11";
CM_ SG_ 2332109725 Reserved_13 "预留预留";
CM_ SG_ 2332109725 M2I_Byrack_IsPostTm_IMM11_13 "绝缘采样时间_IMM11";
CM_ SG_ 2332109725 M2I_Byrack_SysABStTm_IMM11_13 "电压稳定时间_IMM11";
CM_ SG_ 2332109726 CRC_M2I_Byrack_IMM11_14 "CRC校验_IMM11";
CM_ SG_ 2332109726 M2I_Byrack_HVS_IMM11_14 "绝缘测量电压_IMM11";
CM_ SG_ 2332109726 M2I_Byrack_Enable_IMM11_14 "绝缘采样使能位_IMM11";
CM_ SG_ 2332109726 M2I_Byrack_ReVeEnable_IMM11_14 "读取软件版本使能位_IMM11";
CM_ SG_ 2332109726 Reserved_14 "预留预留";
CM_ SG_ 2332109726 M2I_Byrack_IsPostTm_IMM11_14 "绝缘采样时间_IMM11";
CM_ SG_ 2332109726 M2I_Byrack_SysABStTm_IMM11_14 "电压稳定时间_IMM11";
CM_ SG_ 2332109727 CRC_M2I_Byrack_IMM11_15 "CRC校验_IMM11";
CM_ SG_ 2332109727 M2I_Byrack_HVS_IMM11_15 "绝缘测量电压_IMM11";
CM_ SG_ 2332109727 M2I_Byrack_Enable_IMM11_15 "绝缘采样使能位_IMM11";
CM_ SG_ 2332109727 M2I_Byrack_ReVeEnable_IMM11_15 "读取软件版本使能位_IMM11";
CM_ SG_ 2332109727 Reserved_15 "预留预留";
CM_ SG_ 2332109727 M2I_Byrack_IsPostTm_IMM11_15 "绝缘采样时间_IMM11";
CM_ SG_ 2332109727 M2I_Byrack_SysABStTm_IMM11_15 "电压稳定时间_IMM11";
CM_ SG_ 2332109728 CRC_M2I_Byrack_IMM11_16 "CRC校验_IMM11";
CM_ SG_ 2332109728 M2I_Byrack_HVS_IMM11_16 "绝缘测量电压_IMM11";
CM_ SG_ 2332109728 M2I_Byrack_Enable_IMM11_16 "绝缘采样使能位_IMM11";
CM_ SG_ 2332109728 M2I_Byrack_ReVeEnable_IMM11_16 "读取软件版本使能位_IMM11";
CM_ SG_ 2332109728 Reserved_16 "预留预留";
CM_ SG_ 2332109728 M2I_Byrack_IsPostTm_IMM11_16 "绝缘采样时间_IMM11";
CM_ SG_ 2332109728 M2I_Byrack_SysABStTm_IMM11_16 "电压稳定时间_IMM11";
CM_ SG_ 2332109729 CRC_M2I_Byrack_IMM11_17 "CRC校验_IMM11";
CM_ SG_ 2332109729 M2I_Byrack_HVS_IMM11_17 "绝缘测量电压_IMM11";
CM_ SG_ 2332109729 M2I_Byrack_Enable_IMM11_17 "绝缘采样使能位_IMM11";
CM_ SG_ 2332109729 M2I_Byrack_ReVeEnable_IMM11_17 "读取软件版本使能位_IMM11";
CM_ SG_ 2332109729 Reserved_17 "预留预留";
CM_ SG_ 2332109729 M2I_Byrack_IsPostTm_IMM11_17 "绝缘采样时间_IMM11";
CM_ SG_ 2332109729 M2I_Byrack_SysABStTm_IMM11_17 "电压稳定时间_IMM11";
CM_ SG_ 2332109730 CRC_M2I_Byrack_IMM11_18 "CRC校验_IMM11";
CM_ SG_ 2332109730 M2I_Byrack_HVS_IMM11_18 "绝缘测量电压_IMM11";
CM_ SG_ 2332109730 M2I_Byrack_Enable_IMM11_18 "绝缘采样使能位_IMM11";
CM_ SG_ 2332109730 M2I_Byrack_ReVeEnable_IMM11_18 "读取软件版本使能位_IMM11";
CM_ SG_ 2332109730 Reserved_18 "预留预留";
CM_ SG_ 2332109730 M2I_Byrack_IsPostTm_IMM11_18 "绝缘采样时间_IMM11";
CM_ SG_ 2332109730 M2I_Byrack_SysABStTm_IMM11_18 "电压稳定时间_IMM11";
CM_ SG_ 2332109731 CRC_M2I_Byrack_IMM11_19 "CRC校验_IMM11";
CM_ SG_ 2332109731 M2I_Byrack_HVS_IMM11_19 "绝缘测量电压_IMM11";
CM_ SG_ 2332109731 M2I_Byrack_Enable_IMM11_19 "绝缘采样使能位_IMM11";
CM_ SG_ 2332109731 M2I_Byrack_ReVeEnable_IMM11_19 "读取软件版本使能位_IMM11";
CM_ SG_ 2332109731 Reserved_19 "预留预留";
CM_ SG_ 2332109731 M2I_Byrack_IsPostTm_IMM11_19 "绝缘采样时间_IMM11";
CM_ SG_ 2332109731 M2I_Byrack_SysABStTm_IMM11_19 "电压稳定时间_IMM11";
CM_ SG_ 2332109732 CRC_M2I_Byrack_IMM11_20 "CRC校验_IMM11";
CM_ SG_ 2332109732 M2I_Byrack_HVS_IMM11_20 "绝缘测量电压_IMM11";
CM_ SG_ 2332109732 M2I_Byrack_Enable_IMM11_20 "绝缘采样使能位_IMM11";
CM_ SG_ 2332109732 M2I_Byrack_ReVeEnable_IMM11_20 "读取软件版本使能位_IMM11";
CM_ SG_ 2332109732 Reserved_20 "预留预留";
CM_ SG_ 2332109732 M2I_Byrack_IsPostTm_IMM11_20 "绝缘采样时间_IMM11";
CM_ SG_ 2332109732 M2I_Byrack_SysABStTm_IMM11_20 "电压稳定时间_IMM11";
CM_ SG_ 2332109733 CRC_M2I_Byrack_IMM11_21 "CRC校验_IMM11";
CM_ SG_ 2332109733 M2I_Byrack_HVS_IMM11_21 "绝缘测量电压_IMM11";
CM_ SG_ 2332109733 M2I_Byrack_Enable_IMM11_21 "绝缘采样使能位_IMM11";
CM_ SG_ 2332109733 M2I_Byrack_ReVeEnable_IMM11_21 "读取软件版本使能位_IMM11";
CM_ SG_ 2332109733 Reserved_21 "预留预留";
CM_ SG_ 2332109733 M2I_Byrack_IsPostTm_IMM11_21 "绝缘采样时间_IMM11";
CM_ SG_ 2332109733 M2I_Byrack_SysABStTm_IMM11_21 "电压稳定时间_IMM11";
CM_ SG_ 2332109734 CRC_M2I_Byrack_IMM11_22 "CRC校验_IMM11";
CM_ SG_ 2332109734 M2I_Byrack_HVS_IMM11_22 "绝缘测量电压_IMM11";
CM_ SG_ 2332109734 M2I_Byrack_Enable_IMM11_22 "绝缘采样使能位_IMM11";
CM_ SG_ 2332109734 M2I_Byrack_ReVeEnable_IMM11_22 "读取软件版本使能位_IMM11";
CM_ SG_ 2332109734 Reserved_22 "预留预留";
CM_ SG_ 2332109734 M2I_Byrack_IsPostTm_IMM11_22 "绝缘采样时间_IMM11";
CM_ SG_ 2332109734 M2I_Byrack_SysABStTm_IMM11_22 "电压稳定时间_IMM11";
CM_ SG_ 2332109735 CRC_M2I_Byrack_IMM11_23 "CRC校验_IMM11";
CM_ SG_ 2332109735 M2I_Byrack_HVS_IMM11_23 "绝缘测量电压_IMM11";
CM_ SG_ 2332109735 M2I_Byrack_Enable_IMM11_23 "绝缘采样使能位_IMM11";
CM_ SG_ 2332109735 M2I_Byrack_ReVeEnable_IMM11_23 "读取软件版本使能位_IMM11";
CM_ SG_ 2332109735 Reserved_23 "预留预留";
CM_ SG_ 2332109735 M2I_Byrack_IsPostTm_IMM11_23 "绝缘采样时间_IMM11";
CM_ SG_ 2332109735 M2I_Byrack_SysABStTm_IMM11_23 "电压稳定时间_IMM11";
CM_ SG_ 2332109736 CRC_M2I_Byrack_IMM11_24 "CRC校验_IMM11";
CM_ SG_ 2332109736 M2I_Byrack_HVS_IMM11_24 "绝缘测量电压_IMM11";
CM_ SG_ 2332109736 M2I_Byrack_Enable_IMM11_24 "绝缘采样使能位_IMM11";
CM_ SG_ 2332109736 M2I_Byrack_ReVeEnable_IMM11_24 "读取软件版本使能位_IMM11";
CM_ SG_ 2332109736 Reserved_24 "预留预留";
CM_ SG_ 2332109736 M2I_Byrack_IsPostTm_IMM11_24 "绝缘采样时间_IMM11";
CM_ SG_ 2332109736 M2I_Byrack_SysABStTm_IMM11_24 "电压稳定时间_IMM11";
CM_ SG_ 2332109737 CRC_M2I_Byrack_IMM11_25 "CRC校验_IMM11";
CM_ SG_ 2332109737 M2I_Byrack_HVS_IMM11_25 "绝缘测量电压_IMM11";
CM_ SG_ 2332109737 M2I_Byrack_Enable_IMM11_25 "绝缘采样使能位_IMM11";
CM_ SG_ 2332109737 M2I_Byrack_ReVeEnable_IMM11_25 "读取软件版本使能位_IMM11";
CM_ SG_ 2332109737 Reserved_25 "预留预留";
CM_ SG_ 2332109737 M2I_Byrack_IsPostTm_IMM11_25 "绝缘采样时间_IMM11";
CM_ SG_ 2332109737 M2I_Byrack_SysABStTm_IMM11_25 "电压稳定时间_IMM11";
CM_ SG_ 2332109738 CRC_M2I_Byrack_IMM11_26 "CRC校验_IMM11";
CM_ SG_ 2332109738 M2I_Byrack_HVS_IMM11_26 "绝缘测量电压_IMM11";
CM_ SG_ 2332109738 M2I_Byrack_Enable_IMM11_26 "绝缘采样使能位_IMM11";
CM_ SG_ 2332109738 M2I_Byrack_ReVeEnable_IMM11_26 "读取软件版本使能位_IMM11";
CM_ SG_ 2332109738 Reserved_26 "预留预留";
CM_ SG_ 2332109738 M2I_Byrack_IsPostTm_IMM11_26 "绝缘采样时间_IMM11";
CM_ SG_ 2332109738 M2I_Byrack_SysABStTm_IMM11_26 "电压稳定时间_IMM11";
CM_ SG_ 2332109739 CRC_M2I_Byrack_IMM11_27 "CRC校验_IMM11";
CM_ SG_ 2332109739 M2I_Byrack_HVS_IMM11_27 "绝缘测量电压_IMM11";
CM_ SG_ 2332109739 M2I_Byrack_Enable_IMM11_27 "绝缘采样使能位_IMM11";
CM_ SG_ 2332109739 M2I_Byrack_ReVeEnable_IMM11_27 "读取软件版本使能位_IMM11";
CM_ SG_ 2332109739 Reserved_27 "预留预留";
CM_ SG_ 2332109739 M2I_Byrack_IsPostTm_IMM11_27 "绝缘采样时间_IMM11";
CM_ SG_ 2332109739 M2I_Byrack_SysABStTm_IMM11_27 "电压稳定时间_IMM11";
CM_ SG_ 2332109740 CRC_M2I_Byrack_IMM11_28 "CRC校验_IMM11";
CM_ SG_ 2332109740 M2I_Byrack_HVS_IMM11_28 "绝缘测量电压_IMM11";
CM_ SG_ 2332109740 M2I_Byrack_Enable_IMM11_28 "绝缘采样使能位_IMM11";
CM_ SG_ 2332109740 M2I_Byrack_ReVeEnable_IMM11_28 "读取软件版本使能位_IMM11";
CM_ SG_ 2332109740 Reserved_28 "预留预留";
CM_ SG_ 2332109740 M2I_Byrack_IsPostTm_IMM11_28 "绝缘采样时间_IMM11";
CM_ SG_ 2332109740 M2I_Byrack_SysABStTm_IMM11_28 "电压稳定时间_IMM11";
CM_ SG_ 2332109741 CRC_M2I_Byrack_IMM11_29 "CRC校验_IMM11";
CM_ SG_ 2332109741 M2I_Byrack_HVS_IMM11_29 "绝缘测量电压_IMM11";
CM_ SG_ 2332109741 M2I_Byrack_Enable_IMM11_29 "绝缘采样使能位_IMM11";
CM_ SG_ 2332109741 M2I_Byrack_ReVeEnable_IMM11_29 "读取软件版本使能位_IMM11";
CM_ SG_ 2332109741 Reserved_29 "预留预留";
CM_ SG_ 2332109741 M2I_Byrack_IsPostTm_IMM11_29 "绝缘采样时间_IMM11";
CM_ SG_ 2332109741 M2I_Byrack_SysABStTm_IMM11_29 "电压稳定时间_IMM11";
CM_ SG_ 2332109742 CRC_M2I_Byrack_IMM11_30 "CRC校验_IMM11";
CM_ SG_ 2332109742 M2I_Byrack_HVS_IMM11_30 "绝缘测量电压_IMM11";
CM_ SG_ 2332109742 M2I_Byrack_Enable_IMM11_30 "绝缘采样使能位_IMM11";
CM_ SG_ 2332109742 M2I_Byrack_ReVeEnable_IMM11_30 "读取软件版本使能位_IMM11";
CM_ SG_ 2332109742 Reserved_30 "预留预留";
CM_ SG_ 2332109742 M2I_Byrack_IsPostTm_IMM11_30 "绝缘采样时间_IMM11";
CM_ SG_ 2332109742 M2I_Byrack_SysABStTm_IMM11_30 "电压稳定时间_IMM11";
CM_ SG_ 2332109743 CRC_M2I_Byrack_IMM11_31 "CRC校验_IMM11";
CM_ SG_ 2332109743 M2I_Byrack_HVS_IMM11_31 "绝缘测量电压_IMM11";
CM_ SG_ 2332109743 M2I_Byrack_Enable_IMM11_31 "绝缘采样使能位_IMM11";
CM_ SG_ 2332109743 M2I_Byrack_ReVeEnable_IMM11_31 "读取软件版本使能位_IMM11";
CM_ SG_ 2332109743 Reserved_31 "预留预留";
CM_ SG_ 2332109743 M2I_Byrack_IsPostTm_IMM11_31 "绝缘采样时间_IMM11";
CM_ SG_ 2332109743 M2I_Byrack_SysABStTm_IMM11_31 "电压稳定时间_IMM11";
CM_ SG_ 2332109969 CRC_M2I_Byrack_IMM12_01 "CRC校验_IMM12";
CM_ SG_ 2332109969 M2I_Byrack_HVS__IMM12_01 "绝缘测量电压_IMM12";
CM_ SG_ 2332109969 M2I_Byrack_Enable_IMM12_01 "绝缘采样使能位_IMM12";
CM_ SG_ 2332109969 M2I_Byrack_ReVeEnable_IMM12_01 "读取软件版本使能位_IMM12";
CM_ SG_ 2332109969 Reserved_01 "预留预留";
CM_ SG_ 2332109969 M2I_Byrack_IsPostTm_IMM12_01 "绝缘采样时间_IMM12";
CM_ SG_ 2332109969 M2I_Byrack_SysABStTm_IMM12_01 "电压稳定时间_IMM12";
CM_ SG_ 2332109970 CRC_M2I_Byrack_IMM12_02 "CRC校验_IMM12";
CM_ SG_ 2332109970 M2I_Byrack_HVS__IMM12_02 "绝缘测量电压_IMM12";
CM_ SG_ 2332109970 M2I_Byrack_Enable_IMM12_02 "绝缘采样使能位_IMM12";
CM_ SG_ 2332109970 M2I_Byrack_ReVeEnable_IMM12_02 "读取软件版本使能位_IMM12";
CM_ SG_ 2332109970 Reserved_02 "预留预留";
CM_ SG_ 2332109970 M2I_Byrack_IsPostTm_IMM12_02 "绝缘采样时间_IMM12";
CM_ SG_ 2332109970 M2I_Byrack_SysABStTm_IMM12_02 "电压稳定时间_IMM12";
CM_ SG_ 2332109971 CRC_M2I_Byrack_IMM12_03 "CRC校验_IMM12";
CM_ SG_ 2332109971 M2I_Byrack_HVS__IMM12_03 "绝缘测量电压_IMM12";
CM_ SG_ 2332109971 M2I_Byrack_Enable_IMM12_03 "绝缘采样使能位_IMM12";
CM_ SG_ 2332109971 M2I_Byrack_ReVeEnable_IMM12_03 "读取软件版本使能位_IMM12";
CM_ SG_ 2332109971 Reserved_03 "预留预留";
CM_ SG_ 2332109971 M2I_Byrack_IsPostTm_IMM12_03 "绝缘采样时间_IMM12";
CM_ SG_ 2332109971 M2I_Byrack_SysABStTm_IMM12_03 "电压稳定时间_IMM12";
CM_ SG_ 2332109972 CRC_M2I_Byrack_IMM12_04 "CRC校验_IMM12";
CM_ SG_ 2332109972 M2I_Byrack_HVS__IMM12_04 "绝缘测量电压_IMM12";
CM_ SG_ 2332109972 M2I_Byrack_Enable_IMM12_04 "绝缘采样使能位_IMM12";
CM_ SG_ 2332109972 M2I_Byrack_ReVeEnable_IMM12_04 "读取软件版本使能位_IMM12";
CM_ SG_ 2332109972 Reserved_04 "预留预留";
CM_ SG_ 2332109972 M2I_Byrack_IsPostTm_IMM12_04 "绝缘采样时间_IMM12";
CM_ SG_ 2332109972 M2I_Byrack_SysABStTm_IMM12_04 "电压稳定时间_IMM12";
CM_ SG_ 2332109973 CRC_M2I_Byrack_IMM12_05 "CRC校验_IMM12";
CM_ SG_ 2332109973 M2I_Byrack_HVS__IMM12_05 "绝缘测量电压_IMM12";
CM_ SG_ 2332109973 M2I_Byrack_Enable_IMM12_05 "绝缘采样使能位_IMM12";
CM_ SG_ 2332109973 M2I_Byrack_ReVeEnable_IMM12_05 "读取软件版本使能位_IMM12";
CM_ SG_ 2332109973 Reserved_05 "预留预留";
CM_ SG_ 2332109973 M2I_Byrack_IsPostTm_IMM12_05 "绝缘采样时间_IMM12";
CM_ SG_ 2332109973 M2I_Byrack_SysABStTm_IMM12_05 "电压稳定时间_IMM12";
CM_ SG_ 2332109974 CRC_M2I_Byrack_IMM12_06 "CRC校验_IMM12";
CM_ SG_ 2332109974 M2I_Byrack_HVS__IMM12_06 "绝缘测量电压_IMM12";
CM_ SG_ 2332109974 M2I_Byrack_Enable_IMM12_06 "绝缘采样使能位_IMM12";
CM_ SG_ 2332109974 M2I_Byrack_ReVeEnable_IMM12_06 "读取软件版本使能位_IMM12";
CM_ SG_ 2332109974 Reserved_06 "预留预留";
CM_ SG_ 2332109974 M2I_Byrack_IsPostTm_IMM12_06 "绝缘采样时间_IMM12";
CM_ SG_ 2332109974 M2I_Byrack_SysABStTm_IMM12_06 "电压稳定时间_IMM12";
CM_ SG_ 2332109975 CRC_M2I_Byrack_IMM12_07 "CRC校验_IMM12";
CM_ SG_ 2332109975 M2I_Byrack_HVS__IMM12_07 "绝缘测量电压_IMM12";
CM_ SG_ 2332109975 M2I_Byrack_Enable_IMM12_07 "绝缘采样使能位_IMM12";
CM_ SG_ 2332109975 M2I_Byrack_ReVeEnable_IMM12_07 "读取软件版本使能位_IMM12";
CM_ SG_ 2332109975 Reserved_07 "预留预留";
CM_ SG_ 2332109975 M2I_Byrack_IsPostTm_IMM12_07 "绝缘采样时间_IMM12";
CM_ SG_ 2332109975 M2I_Byrack_SysABStTm_IMM12_07 "电压稳定时间_IMM12";
CM_ SG_ 2332109976 CRC_M2I_Byrack_IMM12_08 "CRC校验_IMM12";
CM_ SG_ 2332109976 M2I_Byrack_HVS__IMM12_08 "绝缘测量电压_IMM12";
CM_ SG_ 2332109976 M2I_Byrack_Enable_IMM12_08 "绝缘采样使能位_IMM12";
CM_ SG_ 2332109976 M2I_Byrack_ReVeEnable_IMM12_08 "读取软件版本使能位_IMM12";
CM_ SG_ 2332109976 Reserved_08 "预留预留";
CM_ SG_ 2332109976 M2I_Byrack_IsPostTm_IMM12_08 "绝缘采样时间_IMM12";
CM_ SG_ 2332109976 M2I_Byrack_SysABStTm_IMM12_08 "电压稳定时间_IMM12";
CM_ SG_ 2332109977 CRC_M2I_Byrack_IMM12_09 "CRC校验_IMM12";
CM_ SG_ 2332109977 M2I_Byrack_HVS__IMM12_09 "绝缘测量电压_IMM12";
CM_ SG_ 2332109977 M2I_Byrack_Enable_IMM12_09 "绝缘采样使能位_IMM12";
CM_ SG_ 2332109977 M2I_Byrack_ReVeEnable_IMM12_09 "读取软件版本使能位_IMM12";
CM_ SG_ 2332109977 Reserved_09 "预留预留";
CM_ SG_ 2332109977 M2I_Byrack_IsPostTm_IMM12_09 "绝缘采样时间_IMM12";
CM_ SG_ 2332109977 M2I_Byrack_SysABStTm_IMM12_09 "电压稳定时间_IMM12";
CM_ SG_ 2332109978 CRC_M2I_Byrack_IMM12_10 "CRC校验_IMM12";
CM_ SG_ 2332109978 M2I_Byrack_HVS__IMM12_10 "绝缘测量电压_IMM12";
CM_ SG_ 2332109978 M2I_Byrack_Enable_IMM12_10 "绝缘采样使能位_IMM12";
CM_ SG_ 2332109978 M2I_Byrack_ReVeEnable_IMM12_10 "读取软件版本使能位_IMM12";
CM_ SG_ 2332109978 Reserved_10 "预留预留";
CM_ SG_ 2332109978 M2I_Byrack_IsPostTm_IMM12_10 "绝缘采样时间_IMM12";
CM_ SG_ 2332109978 M2I_Byrack_SysABStTm_IMM12_10 "电压稳定时间_IMM12";
CM_ SG_ 2332109979 CRC_M2I_Byrack_IMM12_11 "CRC校验_IMM12";
CM_ SG_ 2332109979 M2I_Byrack_HVS__IMM12_11 "绝缘测量电压_IMM12";
CM_ SG_ 2332109979 M2I_Byrack_Enable_IMM12_11 "绝缘采样使能位_IMM12";
CM_ SG_ 2332109979 M2I_Byrack_ReVeEnable_IMM12_11 "读取软件版本使能位_IMM12";
CM_ SG_ 2332109979 Reserved_11 "预留预留";
CM_ SG_ 2332109979 M2I_Byrack_IsPostTm_IMM12_11 "绝缘采样时间_IMM12";
CM_ SG_ 2332109979 M2I_Byrack_SysABStTm_IMM12_11 "电压稳定时间_IMM12";
CM_ SG_ 2332109980 CRC_M2I_Byrack_IMM12_12 "CRC校验_IMM12";
CM_ SG_ 2332109980 M2I_Byrack_HVS__IMM12_12 "绝缘测量电压_IMM12";
CM_ SG_ 2332109980 M2I_Byrack_Enable_IMM12_12 "绝缘采样使能位_IMM12";
CM_ SG_ 2332109980 M2I_Byrack_ReVeEnable_IMM12_12 "读取软件版本使能位_IMM12";
CM_ SG_ 2332109980 Reserved_12 "预留预留";
CM_ SG_ 2332109980 M2I_Byrack_IsPostTm_IMM12_12 "绝缘采样时间_IMM12";
CM_ SG_ 2332109980 M2I_Byrack_SysABStTm_IMM12_12 "电压稳定时间_IMM12";
CM_ SG_ 2332109981 CRC_M2I_Byrack_IMM12_13 "CRC校验_IMM12";
CM_ SG_ 2332109981 M2I_Byrack_HVS__IMM12_13 "绝缘测量电压_IMM12";
CM_ SG_ 2332109981 M2I_Byrack_Enable_IMM12_13 "绝缘采样使能位_IMM12";
CM_ SG_ 2332109981 M2I_Byrack_ReVeEnable_IMM12_13 "读取软件版本使能位_IMM12";
CM_ SG_ 2332109981 Reserved_13 "预留预留";
CM_ SG_ 2332109981 M2I_Byrack_IsPostTm_IMM12_13 "绝缘采样时间_IMM12";
CM_ SG_ 2332109981 M2I_Byrack_SysABStTm_IMM12_13 "电压稳定时间_IMM12";
CM_ SG_ 2332109982 CRC_M2I_Byrack_IMM12_14 "CRC校验_IMM12";
CM_ SG_ 2332109982 M2I_Byrack_HVS__IMM12_14 "绝缘测量电压_IMM12";
CM_ SG_ 2332109982 M2I_Byrack_Enable_IMM12_14 "绝缘采样使能位_IMM12";
CM_ SG_ 2332109982 M2I_Byrack_ReVeEnable_IMM12_14 "读取软件版本使能位_IMM12";
CM_ SG_ 2332109982 Reserved_14 "预留预留";
CM_ SG_ 2332109982 M2I_Byrack_IsPostTm_IMM12_14 "绝缘采样时间_IMM12";
CM_ SG_ 2332109982 M2I_Byrack_SysABStTm_IMM12_14 "电压稳定时间_IMM12";
CM_ SG_ 2332109983 CRC_M2I_Byrack_IMM12_15 "CRC校验_IMM12";
CM_ SG_ 2332109983 M2I_Byrack_HVS__IMM12_15 "绝缘测量电压_IMM12";
CM_ SG_ 2332109983 M2I_Byrack_Enable_IMM12_15 "绝缘采样使能位_IMM12";
CM_ SG_ 2332109983 M2I_Byrack_ReVeEnable_IMM12_15 "读取软件版本使能位_IMM12";
CM_ SG_ 2332109983 Reserved_15 "预留预留";
CM_ SG_ 2332109983 M2I_Byrack_IsPostTm_IMM12_15 "绝缘采样时间_IMM12";
CM_ SG_ 2332109983 M2I_Byrack_SysABStTm_IMM12_15 "电压稳定时间_IMM12";
CM_ SG_ 2332109984 CRC_M2I_Byrack_IMM12_16 "CRC校验_IMM12";
CM_ SG_ 2332109984 M2I_Byrack_HVS__IMM12_16 "绝缘测量电压_IMM12";
CM_ SG_ 2332109984 M2I_Byrack_Enable_IMM12_16 "绝缘采样使能位_IMM12";
CM_ SG_ 2332109984 M2I_Byrack_ReVeEnable_IMM12_16 "读取软件版本使能位_IMM12";
CM_ SG_ 2332109984 Reserved_16 "预留预留";
CM_ SG_ 2332109984 M2I_Byrack_IsPostTm_IMM12_16 "绝缘采样时间_IMM12";
CM_ SG_ 2332109984 M2I_Byrack_SysABStTm_IMM12_16 "电压稳定时间_IMM12";
CM_ SG_ 2332109985 CRC_M2I_Byrack_IMM12_17 "CRC校验_IMM12";
CM_ SG_ 2332109985 M2I_Byrack_HVS__IMM12_17 "绝缘测量电压_IMM12";
CM_ SG_ 2332109985 M2I_Byrack_Enable_IMM12_17 "绝缘采样使能位_IMM12";
CM_ SG_ 2332109985 M2I_Byrack_ReVeEnable_IMM12_17 "读取软件版本使能位_IMM12";
CM_ SG_ 2332109985 Reserved_17 "预留预留";
CM_ SG_ 2332109985 M2I_Byrack_IsPostTm_IMM12_17 "绝缘采样时间_IMM12";
CM_ SG_ 2332109985 M2I_Byrack_SysABStTm_IMM12_17 "电压稳定时间_IMM12";
CM_ SG_ 2332109986 CRC_M2I_Byrack_IMM12_18 "CRC校验_IMM12";
CM_ SG_ 2332109986 M2I_Byrack_HVS__IMM12_18 "绝缘测量电压_IMM12";
CM_ SG_ 2332109986 M2I_Byrack_Enable_IMM12_18 "绝缘采样使能位_IMM12";
CM_ SG_ 2332109986 M2I_Byrack_ReVeEnable_IMM12_18 "读取软件版本使能位_IMM12";
CM_ SG_ 2332109986 Reserved_18 "预留预留";
CM_ SG_ 2332109986 M2I_Byrack_IsPostTm_IMM12_18 "绝缘采样时间_IMM12";
CM_ SG_ 2332109986 M2I_Byrack_SysABStTm_IMM12_18 "电压稳定时间_IMM12";
CM_ SG_ 2332109987 CRC_M2I_Byrack_IMM12_19 "CRC校验_IMM12";
CM_ SG_ 2332109987 M2I_Byrack_HVS__IMM12_19 "绝缘测量电压_IMM12";
CM_ SG_ 2332109987 M2I_Byrack_Enable_IMM12_19 "绝缘采样使能位_IMM12";
CM_ SG_ 2332109987 M2I_Byrack_ReVeEnable_IMM12_19 "读取软件版本使能位_IMM12";
CM_ SG_ 2332109987 Reserved_19 "预留预留";
CM_ SG_ 2332109987 M2I_Byrack_IsPostTm_IMM12_19 "绝缘采样时间_IMM12";
CM_ SG_ 2332109987 M2I_Byrack_SysABStTm_IMM12_19 "电压稳定时间_IMM12";
CM_ SG_ 2332109988 CRC_M2I_Byrack_IMM12_20 "CRC校验_IMM12";
CM_ SG_ 2332109988 M2I_Byrack_HVS__IMM12_20 "绝缘测量电压_IMM12";
CM_ SG_ 2332109988 M2I_Byrack_Enable_IMM12_20 "绝缘采样使能位_IMM12";
CM_ SG_ 2332109988 M2I_Byrack_ReVeEnable_IMM12_20 "读取软件版本使能位_IMM12";
CM_ SG_ 2332109988 Reserved_20 "预留预留";
CM_ SG_ 2332109988 M2I_Byrack_IsPostTm_IMM12_20 "绝缘采样时间_IMM12";
CM_ SG_ 2332109988 M2I_Byrack_SysABStTm_IMM12_20 "电压稳定时间_IMM12";
CM_ SG_ 2332109989 CRC_M2I_Byrack_IMM12_21 "CRC校验_IMM12";
CM_ SG_ 2332109989 M2I_Byrack_HVS__IMM12_21 "绝缘测量电压_IMM12";
CM_ SG_ 2332109989 M2I_Byrack_Enable_IMM12_21 "绝缘采样使能位_IMM12";
CM_ SG_ 2332109989 M2I_Byrack_ReVeEnable_IMM12_21 "读取软件版本使能位_IMM12";
CM_ SG_ 2332109989 Reserved_21 "预留预留";
CM_ SG_ 2332109989 M2I_Byrack_IsPostTm_IMM12_21 "绝缘采样时间_IMM12";
CM_ SG_ 2332109989 M2I_Byrack_SysABStTm_IMM12_21 "电压稳定时间_IMM12";
CM_ SG_ 2332109990 CRC_M2I_Byrack_IMM12_22 "CRC校验_IMM12";
CM_ SG_ 2332109990 M2I_Byrack_HVS__IMM12_22 "绝缘测量电压_IMM12";
CM_ SG_ 2332109990 M2I_Byrack_Enable_IMM12_22 "绝缘采样使能位_IMM12";
CM_ SG_ 2332109990 M2I_Byrack_ReVeEnable_IMM12_22 "读取软件版本使能位_IMM12";
CM_ SG_ 2332109990 Reserved_22 "预留预留";
CM_ SG_ 2332109990 M2I_Byrack_IsPostTm_IMM12_22 "绝缘采样时间_IMM12";
CM_ SG_ 2332109990 M2I_Byrack_SysABStTm_IMM12_22 "电压稳定时间_IMM12";
CM_ SG_ 2332109991 CRC_M2I_Byrack_IMM12_23 "CRC校验_IMM12";
CM_ SG_ 2332109991 M2I_Byrack_HVS__IMM12_23 "绝缘测量电压_IMM12";
CM_ SG_ 2332109991 M2I_Byrack_Enable_IMM12_23 "绝缘采样使能位_IMM12";
CM_ SG_ 2332109991 M2I_Byrack_ReVeEnable_IMM12_23 "读取软件版本使能位_IMM12";
CM_ SG_ 2332109991 Reserved_23 "预留预留";
CM_ SG_ 2332109991 M2I_Byrack_IsPostTm_IMM12_23 "绝缘采样时间_IMM12";
CM_ SG_ 2332109991 M2I_Byrack_SysABStTm_IMM12_23 "电压稳定时间_IMM12";
CM_ SG_ 2332109992 CRC_M2I_Byrack_IMM12_24 "CRC校验_IMM12";
CM_ SG_ 2332109992 M2I_Byrack_HVS__IMM12_24 "绝缘测量电压_IMM12";
CM_ SG_ 2332109992 M2I_Byrack_Enable_IMM12_24 "绝缘采样使能位_IMM12";
CM_ SG_ 2332109992 M2I_Byrack_ReVeEnable_IMM12_24 "读取软件版本使能位_IMM12";
CM_ SG_ 2332109992 Reserved_24 "预留预留";
CM_ SG_ 2332109992 M2I_Byrack_IsPostTm_IMM12_24 "绝缘采样时间_IMM12";
CM_ SG_ 2332109992 M2I_Byrack_SysABStTm_IMM12_24 "电压稳定时间_IMM12";
CM_ SG_ 2332109993 CRC_M2I_Byrack_IMM12_25 "CRC校验_IMM12";
CM_ SG_ 2332109993 M2I_Byrack_HVS__IMM12_25 "绝缘测量电压_IMM12";
CM_ SG_ 2332109993 M2I_Byrack_Enable_IMM12_25 "绝缘采样使能位_IMM12";
CM_ SG_ 2332109993 M2I_Byrack_ReVeEnable_IMM12_25 "读取软件版本使能位_IMM12";
CM_ SG_ 2332109993 Reserved_25 "预留预留";
CM_ SG_ 2332109993 M2I_Byrack_IsPostTm_IMM12_25 "绝缘采样时间_IMM12";
CM_ SG_ 2332109993 M2I_Byrack_SysABStTm_IMM12_25 "电压稳定时间_IMM12";
CM_ SG_ 2332109994 CRC_M2I_Byrack_IMM12_26 "CRC校验_IMM12";
CM_ SG_ 2332109994 M2I_Byrack_HVS__IMM12_26 "绝缘测量电压_IMM12";
CM_ SG_ 2332109994 M2I_Byrack_Enable_IMM12_26 "绝缘采样使能位_IMM12";
CM_ SG_ 2332109994 M2I_Byrack_ReVeEnable_IMM12_26 "读取软件版本使能位_IMM12";
CM_ SG_ 2332109994 Reserved_26 "预留预留";
CM_ SG_ 2332109994 M2I_Byrack_IsPostTm_IMM12_26 "绝缘采样时间_IMM12";
CM_ SG_ 2332109994 M2I_Byrack_SysABStTm_IMM12_26 "电压稳定时间_IMM12";
CM_ SG_ 2332109995 CRC_M2I_Byrack_IMM12_27 "CRC校验_IMM12";
CM_ SG_ 2332109995 M2I_Byrack_HVS__IMM12_27 "绝缘测量电压_IMM12";
CM_ SG_ 2332109995 M2I_Byrack_Enable_IMM12_27 "绝缘采样使能位_IMM12";
CM_ SG_ 2332109995 M2I_Byrack_ReVeEnable_IMM12_27 "读取软件版本使能位_IMM12";
CM_ SG_ 2332109995 Reserved_27 "预留预留";
CM_ SG_ 2332109995 M2I_Byrack_IsPostTm_IMM12_27 "绝缘采样时间_IMM12";
CM_ SG_ 2332109995 M2I_Byrack_SysABStTm_IMM12_27 "电压稳定时间_IMM12";
CM_ SG_ 2332109996 CRC_M2I_Byrack_IMM12_28 "CRC校验_IMM12";
CM_ SG_ 2332109996 M2I_Byrack_HVS__IMM12_28 "绝缘测量电压_IMM12";
CM_ SG_ 2332109996 M2I_Byrack_Enable_IMM12_28 "绝缘采样使能位_IMM12";
CM_ SG_ 2332109996 M2I_Byrack_ReVeEnable_IMM12_28 "读取软件版本使能位_IMM12";
CM_ SG_ 2332109996 Reserved_28 "预留预留";
CM_ SG_ 2332109996 M2I_Byrack_IsPostTm_IMM12_28 "绝缘采样时间_IMM12";
CM_ SG_ 2332109996 M2I_Byrack_SysABStTm_IMM12_28 "电压稳定时间_IMM12";
CM_ SG_ 2332109997 CRC_M2I_Byrack_IMM12_29 "CRC校验_IMM12";
CM_ SG_ 2332109997 M2I_Byrack_HVS__IMM12_29 "绝缘测量电压_IMM12";
CM_ SG_ 2332109997 M2I_Byrack_Enable_IMM12_29 "绝缘采样使能位_IMM12";
CM_ SG_ 2332109997 M2I_Byrack_ReVeEnable_IMM12_29 "读取软件版本使能位_IMM12";
CM_ SG_ 2332109997 Reserved_29 "预留预留";
CM_ SG_ 2332109997 M2I_Byrack_IsPostTm_IMM12_29 "绝缘采样时间_IMM12";
CM_ SG_ 2332109997 M2I_Byrack_SysABStTm_IMM12_29 "电压稳定时间_IMM12";
CM_ SG_ 2332109998 CRC_M2I_Byrack_IMM12_30 "CRC校验_IMM12";
CM_ SG_ 2332109998 M2I_Byrack_HVS__IMM12_30 "绝缘测量电压_IMM12";
CM_ SG_ 2332109998 M2I_Byrack_Enable_IMM12_30 "绝缘采样使能位_IMM12";
CM_ SG_ 2332109998 M2I_Byrack_ReVeEnable_IMM12_30 "读取软件版本使能位_IMM12";
CM_ SG_ 2332109998 Reserved_30 "预留预留";
CM_ SG_ 2332109998 M2I_Byrack_IsPostTm_IMM12_30 "绝缘采样时间_IMM12";
CM_ SG_ 2332109998 M2I_Byrack_SysABStTm_IMM12_30 "电压稳定时间_IMM12";
CM_ SG_ 2332109999 CRC_M2I_Byrack_IMM12_31 "CRC校验_IMM12";
CM_ SG_ 2332109999 M2I_Byrack_HVS__IMM12_31 "绝缘测量电压_IMM12";
CM_ SG_ 2332109999 M2I_Byrack_Enable_IMM12_31 "绝缘采样使能位_IMM12";
CM_ SG_ 2332109999 M2I_Byrack_ReVeEnable_IMM12_31 "读取软件版本使能位_IMM12";
CM_ SG_ 2332109999 Reserved_31 "预留预留";
CM_ SG_ 2332109999 M2I_Byrack_IsPostTm_IMM12_31 "绝缘采样时间_IMM12";
CM_ SG_ 2332109999 M2I_Byrack_SysABStTm_IMM12_31 "电压稳定时间_IMM12";
CM_ SG_ 2332110225 CRC_M2I_Byrack_IMM13_01 "CRC校验_IMM13";
CM_ SG_ 2332110225 M2I_Byrack_HVS__IMM13_01 "绝缘测量电压_IMM13";
CM_ SG_ 2332110225 M2I_Byrack_Enable_IMM13_01 "绝缘采样使能位_IMM13";
CM_ SG_ 2332110225 M2I_Byrack_ReVeEnable_IMM13_01 "读取软件版本使能位_IMM13";
CM_ SG_ 2332110225 Reserved_01 "预留预留";
CM_ SG_ 2332110225 M2I_Byrack_IsPostTm_IMM13_01 "绝缘采样时间_IMM13";
CM_ SG_ 2332110225 M2I_Byrack_SysABStTm_IMM13_01 "电压稳定时间_IMM13";
CM_ SG_ 2332110226 CRC_M2I_Byrack_IMM13_02 "CRC校验_IMM13";
CM_ SG_ 2332110226 M2I_Byrack_HVS__IMM13_02 "绝缘测量电压_IMM13";
CM_ SG_ 2332110226 M2I_Byrack_Enable_IMM13_02 "绝缘采样使能位_IMM13";
CM_ SG_ 2332110226 M2I_Byrack_ReVeEnable_IMM13_02 "读取软件版本使能位_IMM13";
CM_ SG_ 2332110226 Reserved_02 "预留预留";
CM_ SG_ 2332110226 M2I_Byrack_IsPostTm_IMM13_02 "绝缘采样时间_IMM13";
CM_ SG_ 2332110226 M2I_Byrack_SysABStTm_IMM13_02 "电压稳定时间_IMM13";
CM_ SG_ 2332110227 CRC_M2I_Byrack_IMM13_03 "CRC校验_IMM13";
CM_ SG_ 2332110227 M2I_Byrack_HVS__IMM13_03 "绝缘测量电压_IMM13";
CM_ SG_ 2332110227 M2I_Byrack_Enable_IMM13_03 "绝缘采样使能位_IMM13";
CM_ SG_ 2332110227 M2I_Byrack_ReVeEnable_IMM13_03 "读取软件版本使能位_IMM13";
CM_ SG_ 2332110227 Reserved_03 "预留预留";
CM_ SG_ 2332110227 M2I_Byrack_IsPostTm_IMM13_03 "绝缘采样时间_IMM13";
CM_ SG_ 2332110227 M2I_Byrack_SysABStTm_IMM13_03 "电压稳定时间_IMM13";
CM_ SG_ 2332110228 CRC_M2I_Byrack_IMM13_04 "CRC校验_IMM13";
CM_ SG_ 2332110228 M2I_Byrack_HVS__IMM13_04 "绝缘测量电压_IMM13";
CM_ SG_ 2332110228 M2I_Byrack_Enable_IMM13_04 "绝缘采样使能位_IMM13";
CM_ SG_ 2332110228 M2I_Byrack_ReVeEnable_IMM13_04 "读取软件版本使能位_IMM13";
CM_ SG_ 2332110228 Reserved_04 "预留预留";
CM_ SG_ 2332110228 M2I_Byrack_IsPostTm_IMM13_04 "绝缘采样时间_IMM13";
CM_ SG_ 2332110228 M2I_Byrack_SysABStTm_IMM13_04 "电压稳定时间_IMM13";
CM_ SG_ 2332110229 CRC_M2I_Byrack_IMM13_05 "CRC校验_IMM13";
CM_ SG_ 2332110229 M2I_Byrack_HVS__IMM13_05 "绝缘测量电压_IMM13";
CM_ SG_ 2332110229 M2I_Byrack_Enable_IMM13_05 "绝缘采样使能位_IMM13";
CM_ SG_ 2332110229 M2I_Byrack_ReVeEnable_IMM13_05 "读取软件版本使能位_IMM13";
CM_ SG_ 2332110229 Reserved_05 "预留预留";
CM_ SG_ 2332110229 M2I_Byrack_IsPostTm_IMM13_05 "绝缘采样时间_IMM13";
CM_ SG_ 2332110229 M2I_Byrack_SysABStTm_IMM13_05 "电压稳定时间_IMM13";
CM_ SG_ 2332110230 CRC_M2I_Byrack_IMM13_06 "CRC校验_IMM13";
CM_ SG_ 2332110230 M2I_Byrack_HVS__IMM13_06 "绝缘测量电压_IMM13";
CM_ SG_ 2332110230 M2I_Byrack_Enable_IMM13_06 "绝缘采样使能位_IMM13";
CM_ SG_ 2332110230 M2I_Byrack_ReVeEnable_IMM13_06 "读取软件版本使能位_IMM13";
CM_ SG_ 2332110230 Reserved_06 "预留预留";
CM_ SG_ 2332110230 M2I_Byrack_IsPostTm_IMM13_06 "绝缘采样时间_IMM13";
CM_ SG_ 2332110230 M2I_Byrack_SysABStTm_IMM13_06 "电压稳定时间_IMM13";
CM_ SG_ 2332110231 CRC_M2I_Byrack_IMM13_07 "CRC校验_IMM13";
CM_ SG_ 2332110231 M2I_Byrack_HVS__IMM13_07 "绝缘测量电压_IMM13";
CM_ SG_ 2332110231 M2I_Byrack_Enable_IMM13_07 "绝缘采样使能位_IMM13";
CM_ SG_ 2332110231 M2I_Byrack_ReVeEnable_IMM13_07 "读取软件版本使能位_IMM13";
CM_ SG_ 2332110231 Reserved_07 "预留预留";
CM_ SG_ 2332110231 M2I_Byrack_IsPostTm_IMM13_07 "绝缘采样时间_IMM13";
CM_ SG_ 2332110231 M2I_Byrack_SysABStTm_IMM13_07 "电压稳定时间_IMM13";
CM_ SG_ 2332110232 CRC_M2I_Byrack_IMM13_08 "CRC校验_IMM13";
CM_ SG_ 2332110232 M2I_Byrack_HVS__IMM13_08 "绝缘测量电压_IMM13";
CM_ SG_ 2332110232 M2I_Byrack_Enable_IMM13_08 "绝缘采样使能位_IMM13";
CM_ SG_ 2332110232 M2I_Byrack_ReVeEnable_IMM13_08 "读取软件版本使能位_IMM13";
CM_ SG_ 2332110232 Reserved_08 "预留预留";
CM_ SG_ 2332110232 M2I_Byrack_IsPostTm_IMM13_08 "绝缘采样时间_IMM13";
CM_ SG_ 2332110232 M2I_Byrack_SysABStTm_IMM13_08 "电压稳定时间_IMM13";
CM_ SG_ 2332110233 CRC_M2I_Byrack_IMM13_09 "CRC校验_IMM13";
CM_ SG_ 2332110233 M2I_Byrack_HVS__IMM13_09 "绝缘测量电压_IMM13";
CM_ SG_ 2332110233 M2I_Byrack_Enable_IMM13_09 "绝缘采样使能位_IMM13";
CM_ SG_ 2332110233 M2I_Byrack_ReVeEnable_IMM13_09 "读取软件版本使能位_IMM13";
CM_ SG_ 2332110233 Reserved_09 "预留预留";
CM_ SG_ 2332110233 M2I_Byrack_IsPostTm_IMM13_09 "绝缘采样时间_IMM13";
CM_ SG_ 2332110233 M2I_Byrack_SysABStTm_IMM13_09 "电压稳定时间_IMM13";
CM_ SG_ 2332110234 CRC_M2I_Byrack_IMM13_10 "CRC校验_IMM13";
CM_ SG_ 2332110234 M2I_Byrack_HVS__IMM13_10 "绝缘测量电压_IMM13";
CM_ SG_ 2332110234 M2I_Byrack_Enable_IMM13_10 "绝缘采样使能位_IMM13";
CM_ SG_ 2332110234 M2I_Byrack_ReVeEnable_IMM13_10 "读取软件版本使能位_IMM13";
CM_ SG_ 2332110234 Reserved_10 "预留预留";
CM_ SG_ 2332110234 M2I_Byrack_IsPostTm_IMM13_10 "绝缘采样时间_IMM13";
CM_ SG_ 2332110234 M2I_Byrack_SysABStTm_IMM13_10 "电压稳定时间_IMM13";
CM_ SG_ 2332110235 CRC_M2I_Byrack_IMM13_11 "CRC校验_IMM13";
CM_ SG_ 2332110235 M2I_Byrack_HVS__IMM13_11 "绝缘测量电压_IMM13";
CM_ SG_ 2332110235 M2I_Byrack_Enable_IMM13_11 "绝缘采样使能位_IMM13";
CM_ SG_ 2332110235 M2I_Byrack_ReVeEnable_IMM13_11 "读取软件版本使能位_IMM13";
CM_ SG_ 2332110235 Reserved_11 "预留预留";
CM_ SG_ 2332110235 M2I_Byrack_IsPostTm_IMM13_11 "绝缘采样时间_IMM13";
CM_ SG_ 2332110235 M2I_Byrack_SysABStTm_IMM13_11 "电压稳定时间_IMM13";
CM_ SG_ 2332110236 CRC_M2I_Byrack_IMM13_12 "CRC校验_IMM13";
CM_ SG_ 2332110236 M2I_Byrack_HVS__IMM13_12 "绝缘测量电压_IMM13";
CM_ SG_ 2332110236 M2I_Byrack_Enable_IMM13_12 "绝缘采样使能位_IMM13";
CM_ SG_ 2332110236 M2I_Byrack_ReVeEnable_IMM13_12 "读取软件版本使能位_IMM13";
CM_ SG_ 2332110236 Reserved_12 "预留预留";
CM_ SG_ 2332110236 M2I_Byrack_IsPostTm_IMM13_12 "绝缘采样时间_IMM13";
CM_ SG_ 2332110236 M2I_Byrack_SysABStTm_IMM13_12 "电压稳定时间_IMM13";
CM_ SG_ 2332110237 CRC_M2I_Byrack_IMM13_13 "CRC校验_IMM13";
CM_ SG_ 2332110237 M2I_Byrack_HVS__IMM13_13 "绝缘测量电压_IMM13";
CM_ SG_ 2332110237 M2I_Byrack_Enable_IMM13_13 "绝缘采样使能位_IMM13";
CM_ SG_ 2332110237 M2I_Byrack_ReVeEnable_IMM13_13 "读取软件版本使能位_IMM13";
CM_ SG_ 2332110237 Reserved_13 "预留预留";
CM_ SG_ 2332110237 M2I_Byrack_IsPostTm_IMM13_13 "绝缘采样时间_IMM13";
CM_ SG_ 2332110237 M2I_Byrack_SysABStTm_IMM13_13 "电压稳定时间_IMM13";
CM_ SG_ 2332110238 CRC_M2I_Byrack_IMM13_14 "CRC校验_IMM13";
CM_ SG_ 2332110238 M2I_Byrack_HVS__IMM13_14 "绝缘测量电压_IMM13";
CM_ SG_ 2332110238 M2I_Byrack_Enable_IMM13_14 "绝缘采样使能位_IMM13";
CM_ SG_ 2332110238 M2I_Byrack_ReVeEnable_IMM13_14 "读取软件版本使能位_IMM13";
CM_ SG_ 2332110238 Reserved_14 "预留预留";
CM_ SG_ 2332110238 M2I_Byrack_IsPostTm_IMM13_14 "绝缘采样时间_IMM13";
CM_ SG_ 2332110238 M2I_Byrack_SysABStTm_IMM13_14 "电压稳定时间_IMM13";
CM_ SG_ 2332110239 CRC_M2I_Byrack_IMM13_15 "CRC校验_IMM13";
CM_ SG_ 2332110239 M2I_Byrack_HVS__IMM13_15 "绝缘测量电压_IMM13";
CM_ SG_ 2332110239 M2I_Byrack_Enable_IMM13_15 "绝缘采样使能位_IMM13";
CM_ SG_ 2332110239 M2I_Byrack_ReVeEnable_IMM13_15 "读取软件版本使能位_IMM13";
CM_ SG_ 2332110239 Reserved_15 "预留预留";
CM_ SG_ 2332110239 M2I_Byrack_IsPostTm_IMM13_15 "绝缘采样时间_IMM13";
CM_ SG_ 2332110239 M2I_Byrack_SysABStTm_IMM13_15 "电压稳定时间_IMM13";
CM_ SG_ 2332110240 CRC_M2I_Byrack_IMM13_16 "CRC校验_IMM13";
CM_ SG_ 2332110240 M2I_Byrack_HVS__IMM13_16 "绝缘测量电压_IMM13";
CM_ SG_ 2332110240 M2I_Byrack_Enable_IMM13_16 "绝缘采样使能位_IMM13";
CM_ SG_ 2332110240 M2I_Byrack_ReVeEnable_IMM13_16 "读取软件版本使能位_IMM13";
CM_ SG_ 2332110240 Reserved_16 "预留预留";
CM_ SG_ 2332110240 M2I_Byrack_IsPostTm_IMM13_16 "绝缘采样时间_IMM13";
CM_ SG_ 2332110240 M2I_Byrack_SysABStTm_IMM13_16 "电压稳定时间_IMM13";
CM_ SG_ 2332110241 CRC_M2I_Byrack_IMM13_17 "CRC校验_IMM13";
CM_ SG_ 2332110241 M2I_Byrack_HVS__IMM13_17 "绝缘测量电压_IMM13";
CM_ SG_ 2332110241 M2I_Byrack_Enable_IMM13_17 "绝缘采样使能位_IMM13";
CM_ SG_ 2332110241 M2I_Byrack_ReVeEnable_IMM13_17 "读取软件版本使能位_IMM13";
CM_ SG_ 2332110241 Reserved_17 "预留预留";
CM_ SG_ 2332110241 M2I_Byrack_IsPostTm_IMM13_17 "绝缘采样时间_IMM13";
CM_ SG_ 2332110241 M2I_Byrack_SysABStTm_IMM13_17 "电压稳定时间_IMM13";
CM_ SG_ 2332110242 CRC_M2I_Byrack_IMM13_18 "CRC校验_IMM13";
CM_ SG_ 2332110242 M2I_Byrack_HVS__IMM13_18 "绝缘测量电压_IMM13";
CM_ SG_ 2332110242 M2I_Byrack_Enable_IMM13_18 "绝缘采样使能位_IMM13";
CM_ SG_ 2332110242 M2I_Byrack_ReVeEnable_IMM13_18 "读取软件版本使能位_IMM13";
CM_ SG_ 2332110242 Reserved_18 "预留预留";
CM_ SG_ 2332110242 M2I_Byrack_IsPostTm_IMM13_18 "绝缘采样时间_IMM13";
CM_ SG_ 2332110242 M2I_Byrack_SysABStTm_IMM13_18 "电压稳定时间_IMM13";
CM_ SG_ 2332110243 CRC_M2I_Byrack_IMM13_19 "CRC校验_IMM13";
CM_ SG_ 2332110243 M2I_Byrack_HVS__IMM13_19 "绝缘测量电压_IMM13";
CM_ SG_ 2332110243 M2I_Byrack_Enable_IMM13_19 "绝缘采样使能位_IMM13";
CM_ SG_ 2332110243 M2I_Byrack_ReVeEnable_IMM13_19 "读取软件版本使能位_IMM13";
CM_ SG_ 2332110243 Reserved_19 "预留预留";
CM_ SG_ 2332110243 M2I_Byrack_IsPostTm_IMM13_19 "绝缘采样时间_IMM13";
CM_ SG_ 2332110243 M2I_Byrack_SysABStTm_IMM13_19 "电压稳定时间_IMM13";
CM_ SG_ 2332110244 CRC_M2I_Byrack_IMM13_20 "CRC校验_IMM13";
CM_ SG_ 2332110244 M2I_Byrack_HVS__IMM13_20 "绝缘测量电压_IMM13";
CM_ SG_ 2332110244 M2I_Byrack_Enable_IMM13_20 "绝缘采样使能位_IMM13";
CM_ SG_ 2332110244 M2I_Byrack_ReVeEnable_IMM13_20 "读取软件版本使能位_IMM13";
CM_ SG_ 2332110244 Reserved_20 "预留预留";
CM_ SG_ 2332110244 M2I_Byrack_IsPostTm_IMM13_20 "绝缘采样时间_IMM13";
CM_ SG_ 2332110244 M2I_Byrack_SysABStTm_IMM13_20 "电压稳定时间_IMM13";
CM_ SG_ 2332110245 CRC_M2I_Byrack_IMM13_21 "CRC校验_IMM13";
CM_ SG_ 2332110245 M2I_Byrack_HVS__IMM13_21 "绝缘测量电压_IMM13";
CM_ SG_ 2332110245 M2I_Byrack_Enable_IMM13_21 "绝缘采样使能位_IMM13";
CM_ SG_ 2332110245 M2I_Byrack_ReVeEnable_IMM13_21 "读取软件版本使能位_IMM13";
CM_ SG_ 2332110245 Reserved_21 "预留预留";
CM_ SG_ 2332110245 M2I_Byrack_IsPostTm_IMM13_21 "绝缘采样时间_IMM13";
CM_ SG_ 2332110245 M2I_Byrack_SysABStTm_IMM13_21 "电压稳定时间_IMM13";
CM_ SG_ 2332110246 CRC_M2I_Byrack_IMM13_22 "CRC校验_IMM13";
CM_ SG_ 2332110246 M2I_Byrack_HVS__IMM13_22 "绝缘测量电压_IMM13";
CM_ SG_ 2332110246 M2I_Byrack_Enable_IMM13_22 "绝缘采样使能位_IMM13";
CM_ SG_ 2332110246 M2I_Byrack_ReVeEnable_IMM13_22 "读取软件版本使能位_IMM13";
CM_ SG_ 2332110246 Reserved_22 "预留预留";
CM_ SG_ 2332110246 M2I_Byrack_IsPostTm_IMM13_22 "绝缘采样时间_IMM13";
CM_ SG_ 2332110246 M2I_Byrack_SysABStTm_IMM13_22 "电压稳定时间_IMM13";
CM_ SG_ 2332110247 CRC_M2I_Byrack_IMM13_23 "CRC校验_IMM13";
CM_ SG_ 2332110247 M2I_Byrack_HVS__IMM13_23 "绝缘测量电压_IMM13";
CM_ SG_ 2332110247 M2I_Byrack_Enable_IMM13_23 "绝缘采样使能位_IMM13";
CM_ SG_ 2332110247 M2I_Byrack_ReVeEnable_IMM13_23 "读取软件版本使能位_IMM13";
CM_ SG_ 2332110247 Reserved_23 "预留预留";
CM_ SG_ 2332110247 M2I_Byrack_IsPostTm_IMM13_23 "绝缘采样时间_IMM13";
CM_ SG_ 2332110247 M2I_Byrack_SysABStTm_IMM13_23 "电压稳定时间_IMM13";
CM_ SG_ 2332110248 CRC_M2I_Byrack_IMM13_24 "CRC校验_IMM13";
CM_ SG_ 2332110248 M2I_Byrack_HVS__IMM13_24 "绝缘测量电压_IMM13";
CM_ SG_ 2332110248 M2I_Byrack_Enable_IMM13_24 "绝缘采样使能位_IMM13";
CM_ SG_ 2332110248 M2I_Byrack_ReVeEnable_IMM13_24 "读取软件版本使能位_IMM13";
CM_ SG_ 2332110248 Reserved_24 "预留预留";
CM_ SG_ 2332110248 M2I_Byrack_IsPostTm_IMM13_24 "绝缘采样时间_IMM13";
CM_ SG_ 2332110248 M2I_Byrack_SysABStTm_IMM13_24 "电压稳定时间_IMM13";
CM_ SG_ 2332110249 CRC_M2I_Byrack_IMM13_25 "CRC校验_IMM13";
CM_ SG_ 2332110249 M2I_Byrack_HVS__IMM13_25 "绝缘测量电压_IMM13";
CM_ SG_ 2332110249 M2I_Byrack_Enable_IMM13_25 "绝缘采样使能位_IMM13";
CM_ SG_ 2332110249 M2I_Byrack_ReVeEnable_IMM13_25 "读取软件版本使能位_IMM13";
CM_ SG_ 2332110249 Reserved_25 "预留预留";
CM_ SG_ 2332110249 M2I_Byrack_IsPostTm_IMM13_25 "绝缘采样时间_IMM13";
CM_ SG_ 2332110249 M2I_Byrack_SysABStTm_IMM13_25 "电压稳定时间_IMM13";
CM_ SG_ 2332110250 CRC_M2I_Byrack_IMM13_26 "CRC校验_IMM13";
CM_ SG_ 2332110250 M2I_Byrack_HVS__IMM13_26 "绝缘测量电压_IMM13";
CM_ SG_ 2332110250 M2I_Byrack_Enable_IMM13_26 "绝缘采样使能位_IMM13";
CM_ SG_ 2332110250 M2I_Byrack_ReVeEnable_IMM13_26 "读取软件版本使能位_IMM13";
CM_ SG_ 2332110250 Reserved_26 "预留预留";
CM_ SG_ 2332110250 M2I_Byrack_IsPostTm_IMM13_26 "绝缘采样时间_IMM13";
CM_ SG_ 2332110250 M2I_Byrack_SysABStTm_IMM13_26 "电压稳定时间_IMM13";
CM_ SG_ 2332110251 CRC_M2I_Byrack_IMM13_27 "CRC校验_IMM13";
CM_ SG_ 2332110251 M2I_Byrack_HVS__IMM13_27 "绝缘测量电压_IMM13";
CM_ SG_ 2332110251 M2I_Byrack_Enable_IMM13_27 "绝缘采样使能位_IMM13";
CM_ SG_ 2332110251 M2I_Byrack_ReVeEnable_IMM13_27 "读取软件版本使能位_IMM13";
CM_ SG_ 2332110251 Reserved_27 "预留预留";
CM_ SG_ 2332110251 M2I_Byrack_IsPostTm_IMM13_27 "绝缘采样时间_IMM13";
CM_ SG_ 2332110251 M2I_Byrack_SysABStTm_IMM13_27 "电压稳定时间_IMM13";
CM_ SG_ 2332110252 CRC_M2I_Byrack_IMM13_28 "CRC校验_IMM13";
CM_ SG_ 2332110252 M2I_Byrack_HVS__IMM13_28 "绝缘测量电压_IMM13";
CM_ SG_ 2332110252 M2I_Byrack_Enable_IMM13_28 "绝缘采样使能位_IMM13";
CM_ SG_ 2332110252 M2I_Byrack_ReVeEnable_IMM13_28 "读取软件版本使能位_IMM13";
CM_ SG_ 2332110252 Reserved_28 "预留预留";
CM_ SG_ 2332110252 M2I_Byrack_IsPostTm_IMM13_28 "绝缘采样时间_IMM13";
CM_ SG_ 2332110252 M2I_Byrack_SysABStTm_IMM13_28 "电压稳定时间_IMM13";
CM_ SG_ 2332110253 CRC_M2I_Byrack_IMM13_29 "CRC校验_IMM13";
CM_ SG_ 2332110253 M2I_Byrack_HVS__IMM13_29 "绝缘测量电压_IMM13";
CM_ SG_ 2332110253 M2I_Byrack_Enable_IMM13_29 "绝缘采样使能位_IMM13";
CM_ SG_ 2332110253 M2I_Byrack_ReVeEnable_IMM13_29 "读取软件版本使能位_IMM13";
CM_ SG_ 2332110253 Reserved_29 "预留预留";
CM_ SG_ 2332110253 M2I_Byrack_IsPostTm_IMM13_29 "绝缘采样时间_IMM13";
CM_ SG_ 2332110253 M2I_Byrack_SysABStTm_IMM13_29 "电压稳定时间_IMM13";
CM_ SG_ 2332110254 CRC_M2I_Byrack_IMM13_30 "CRC校验_IMM13";
CM_ SG_ 2332110254 M2I_Byrack_HVS__IMM13_30 "绝缘测量电压_IMM13";
CM_ SG_ 2332110254 M2I_Byrack_Enable_IMM13_30 "绝缘采样使能位_IMM13";
CM_ SG_ 2332110254 M2I_Byrack_ReVeEnable_IMM13_30 "读取软件版本使能位_IMM13";
CM_ SG_ 2332110254 Reserved_30 "预留预留";
CM_ SG_ 2332110254 M2I_Byrack_IsPostTm_IMM13_30 "绝缘采样时间_IMM13";
CM_ SG_ 2332110254 M2I_Byrack_SysABStTm_IMM13_30 "电压稳定时间_IMM13";
CM_ SG_ 2332110255 CRC_M2I_Byrack_IMM13_31 "CRC校验_IMM13";
CM_ SG_ 2332110255 M2I_Byrack_HVS__IMM13_31 "绝缘测量电压_IMM13";
CM_ SG_ 2332110255 M2I_Byrack_Enable_IMM13_31 "绝缘采样使能位_IMM13";
CM_ SG_ 2332110255 M2I_Byrack_ReVeEnable_IMM13_31 "读取软件版本使能位_IMM13";
CM_ SG_ 2332110255 Reserved_31 "预留预留";
CM_ SG_ 2332110255 M2I_Byrack_IsPostTm_IMM13_31 "绝缘采样时间_IMM13";
CM_ SG_ 2332110255 M2I_Byrack_SysABStTm_IMM13_31 "电压稳定时间_IMM13";
CM_ SG_ 2332110481 CRC_M2I_Byrack_IMM14_01 "CRC校验_IMM14";
CM_ SG_ 2332110481 M2I_Byrack_HVS_IMM14_01 "绝缘测量电压_IMM14";
CM_ SG_ 2332110481 M2I_Byrack_Enable_IMM14_01 "绝缘采样使能位_IMM14";
CM_ SG_ 2332110481 M2I_Byrack_ReVeEnable_IMM14_01 "读取软件版本使能位_IMM14";
CM_ SG_ 2332110481 Reserved_01 "预留预留";
CM_ SG_ 2332110481 M2I_Byrack_IsPostTm_IMM14_01 "绝缘采样时间_IMM14";
CM_ SG_ 2332110481 M2I_Byrack_SysABStTm_IMM14_01 "电压稳定时间_IMM14";
CM_ SG_ 2332110482 CRC_M2I_Byrack_IMM14_02 "CRC校验_IMM14";
CM_ SG_ 2332110482 M2I_Byrack_HVS_IMM14_02 "绝缘测量电压_IMM14";
CM_ SG_ 2332110482 M2I_Byrack_Enable_IMM14_02 "绝缘采样使能位_IMM14";
CM_ SG_ 2332110482 M2I_Byrack_ReVeEnable_IMM14_02 "读取软件版本使能位_IMM14";
CM_ SG_ 2332110482 Reserved_02 "预留预留";
CM_ SG_ 2332110482 M2I_Byrack_IsPostTm_IMM14_02 "绝缘采样时间_IMM14";
CM_ SG_ 2332110482 M2I_Byrack_SysABStTm_IMM14_02 "电压稳定时间_IMM14";
CM_ SG_ 2332110483 CRC_M2I_Byrack_IMM14_03 "CRC校验_IMM14";
CM_ SG_ 2332110483 M2I_Byrack_HVS_IMM14_03 "绝缘测量电压_IMM14";
CM_ SG_ 2332110483 M2I_Byrack_Enable_IMM14_03 "绝缘采样使能位_IMM14";
CM_ SG_ 2332110483 M2I_Byrack_ReVeEnable_IMM14_03 "读取软件版本使能位_IMM14";
CM_ SG_ 2332110483 Reserved_03 "预留预留";
CM_ SG_ 2332110483 M2I_Byrack_IsPostTm_IMM14_03 "绝缘采样时间_IMM14";
CM_ SG_ 2332110483 M2I_Byrack_SysABStTm_IMM14_03 "电压稳定时间_IMM14";
CM_ SG_ 2332110484 CRC_M2I_Byrack_IMM14_04 "CRC校验_IMM14";
CM_ SG_ 2332110484 M2I_Byrack_HVS_IMM14_04 "绝缘测量电压_IMM14";
CM_ SG_ 2332110484 M2I_Byrack_Enable_IMM14_04 "绝缘采样使能位_IMM14";
CM_ SG_ 2332110484 M2I_Byrack_ReVeEnable_IMM14_04 "读取软件版本使能位_IMM14";
CM_ SG_ 2332110484 Reserved_04 "预留预留";
CM_ SG_ 2332110484 M2I_Byrack_IsPostTm_IMM14_04 "绝缘采样时间_IMM14";
CM_ SG_ 2332110484 M2I_Byrack_SysABStTm_IMM14_04 "电压稳定时间_IMM14";
CM_ SG_ 2332110485 CRC_M2I_Byrack_IMM14_05 "CRC校验_IMM14";
CM_ SG_ 2332110485 M2I_Byrack_HVS_IMM14_05 "绝缘测量电压_IMM14";
CM_ SG_ 2332110485 M2I_Byrack_Enable_IMM14_05 "绝缘采样使能位_IMM14";
CM_ SG_ 2332110485 M2I_Byrack_ReVeEnable_IMM14_05 "读取软件版本使能位_IMM14";
CM_ SG_ 2332110485 Reserved_05 "预留预留";
CM_ SG_ 2332110485 M2I_Byrack_IsPostTm_IMM14_05 "绝缘采样时间_IMM14";
CM_ SG_ 2332110485 M2I_Byrack_SysABStTm_IMM14_05 "电压稳定时间_IMM14";
CM_ SG_ 2332110486 CRC_M2I_Byrack_IMM14_06 "CRC校验_IMM14";
CM_ SG_ 2332110486 M2I_Byrack_HVS_IMM14_06 "绝缘测量电压_IMM14";
CM_ SG_ 2332110486 M2I_Byrack_Enable_IMM14_06 "绝缘采样使能位_IMM14";
CM_ SG_ 2332110486 M2I_Byrack_ReVeEnable_IMM14_06 "读取软件版本使能位_IMM14";
CM_ SG_ 2332110486 Reserved_06 "预留预留";
CM_ SG_ 2332110486 M2I_Byrack_IsPostTm_IMM14_06 "绝缘采样时间_IMM14";
CM_ SG_ 2332110486 M2I_Byrack_SysABStTm_IMM14_06 "电压稳定时间_IMM14";
CM_ SG_ 2332110487 CRC_M2I_Byrack_IMM14_07 "CRC校验_IMM14";
CM_ SG_ 2332110487 M2I_Byrack_HVS_IMM14_07 "绝缘测量电压_IMM14";
CM_ SG_ 2332110487 M2I_Byrack_Enable_IMM14_07 "绝缘采样使能位_IMM14";
CM_ SG_ 2332110487 M2I_Byrack_ReVeEnable_IMM14_07 "读取软件版本使能位_IMM14";
CM_ SG_ 2332110487 Reserved_07 "预留预留";
CM_ SG_ 2332110487 M2I_Byrack_IsPostTm_IMM14_07 "绝缘采样时间_IMM14";
CM_ SG_ 2332110487 M2I_Byrack_SysABStTm_IMM14_07 "电压稳定时间_IMM14";
CM_ SG_ 2332110488 CRC_M2I_Byrack_IMM14_08 "CRC校验_IMM14";
CM_ SG_ 2332110488 M2I_Byrack_HVS_IMM14_08 "绝缘测量电压_IMM14";
CM_ SG_ 2332110488 M2I_Byrack_Enable_IMM14_08 "绝缘采样使能位_IMM14";
CM_ SG_ 2332110488 M2I_Byrack_ReVeEnable_IMM14_08 "读取软件版本使能位_IMM14";
CM_ SG_ 2332110488 Reserved_08 "预留预留";
CM_ SG_ 2332110488 M2I_Byrack_IsPostTm_IMM14_08 "绝缘采样时间_IMM14";
CM_ SG_ 2332110488 M2I_Byrack_SysABStTm_IMM14_08 "电压稳定时间_IMM14";
CM_ SG_ 2332110489 CRC_M2I_Byrack_IMM14_09 "CRC校验_IMM14";
CM_ SG_ 2332110489 M2I_Byrack_HVS_IMM14_09 "绝缘测量电压_IMM14";
CM_ SG_ 2332110489 M2I_Byrack_Enable_IMM14_09 "绝缘采样使能位_IMM14";
CM_ SG_ 2332110489 M2I_Byrack_ReVeEnable_IMM14_09 "读取软件版本使能位_IMM14";
CM_ SG_ 2332110489 Reserved_09 "预留预留";
CM_ SG_ 2332110489 M2I_Byrack_IsPostTm_IMM14_09 "绝缘采样时间_IMM14";
CM_ SG_ 2332110489 M2I_Byrack_SysABStTm_IMM14_09 "电压稳定时间_IMM14";
CM_ SG_ 2332110490 CRC_M2I_Byrack_IMM14_10 "CRC校验_IMM14";
CM_ SG_ 2332110490 M2I_Byrack_HVS_IMM14_10 "绝缘测量电压_IMM14";
CM_ SG_ 2332110490 M2I_Byrack_Enable_IMM14_10 "绝缘采样使能位_IMM14";
CM_ SG_ 2332110490 M2I_Byrack_ReVeEnable_IMM14_10 "读取软件版本使能位_IMM14";
CM_ SG_ 2332110490 Reserved_10 "预留预留";
CM_ SG_ 2332110490 M2I_Byrack_IsPostTm_IMM14_10 "绝缘采样时间_IMM14";
CM_ SG_ 2332110490 M2I_Byrack_SysABStTm_IMM14_10 "电压稳定时间_IMM14";
CM_ SG_ 2332110491 CRC_M2I_Byrack_IMM14_11 "CRC校验_IMM14";
CM_ SG_ 2332110491 M2I_Byrack_HVS_IMM14_11 "绝缘测量电压_IMM14";
CM_ SG_ 2332110491 M2I_Byrack_Enable_IMM14_11 "绝缘采样使能位_IMM14";
CM_ SG_ 2332110491 M2I_Byrack_ReVeEnable_IMM14_11 "读取软件版本使能位_IMM14";
CM_ SG_ 2332110491 Reserved_11 "预留预留";
CM_ SG_ 2332110491 M2I_Byrack_IsPostTm_IMM14_11 "绝缘采样时间_IMM14";
CM_ SG_ 2332110491 M2I_Byrack_SysABStTm_IMM14_11 "电压稳定时间_IMM14";
CM_ SG_ 2332110492 CRC_M2I_Byrack_IMM14_12 "CRC校验_IMM14";
CM_ SG_ 2332110492 M2I_Byrack_HVS_IMM14_12 "绝缘测量电压_IMM14";
CM_ SG_ 2332110492 M2I_Byrack_Enable_IMM14_12 "绝缘采样使能位_IMM14";
CM_ SG_ 2332110492 M2I_Byrack_ReVeEnable_IMM14_12 "读取软件版本使能位_IMM14";
CM_ SG_ 2332110492 Reserved_12 "预留预留";
CM_ SG_ 2332110492 M2I_Byrack_IsPostTm_IMM14_12 "绝缘采样时间_IMM14";
CM_ SG_ 2332110492 M2I_Byrack_SysABStTm_IMM14_12 "电压稳定时间_IMM14";
CM_ SG_ 2332110493 CRC_M2I_Byrack_IMM14_13 "CRC校验_IMM14";
CM_ SG_ 2332110493 M2I_Byrack_HVS_IMM14_13 "绝缘测量电压_IMM14";
CM_ SG_ 2332110493 M2I_Byrack_Enable_IMM14_13 "绝缘采样使能位_IMM14";
CM_ SG_ 2332110493 M2I_Byrack_ReVeEnable_IMM14_13 "读取软件版本使能位_IMM14";
CM_ SG_ 2332110493 Reserved_13 "预留预留";
CM_ SG_ 2332110493 M2I_Byrack_IsPostTm_IMM14_13 "绝缘采样时间_IMM14";
CM_ SG_ 2332110493 M2I_Byrack_SysABStTm_IMM14_13 "电压稳定时间_IMM14";
CM_ SG_ 2332110494 CRC_M2I_Byrack_IMM14_14 "CRC校验_IMM14";
CM_ SG_ 2332110494 M2I_Byrack_HVS_IMM14_14 "绝缘测量电压_IMM14";
CM_ SG_ 2332110494 M2I_Byrack_Enable_IMM14_14 "绝缘采样使能位_IMM14";
CM_ SG_ 2332110494 M2I_Byrack_ReVeEnable_IMM14_14 "读取软件版本使能位_IMM14";
CM_ SG_ 2332110494 Reserved_14 "预留预留";
CM_ SG_ 2332110494 M2I_Byrack_IsPostTm_IMM14_14 "绝缘采样时间_IMM14";
CM_ SG_ 2332110494 M2I_Byrack_SysABStTm_IMM14_14 "电压稳定时间_IMM14";
CM_ SG_ 2332110495 CRC_M2I_Byrack_IMM14_15 "CRC校验_IMM14";
CM_ SG_ 2332110495 M2I_Byrack_HVS_IMM14_15 "绝缘测量电压_IMM14";
CM_ SG_ 2332110495 M2I_Byrack_Enable_IMM14_15 "绝缘采样使能位_IMM14";
CM_ SG_ 2332110495 M2I_Byrack_ReVeEnable_IMM14_15 "读取软件版本使能位_IMM14";
CM_ SG_ 2332110495 Reserved_15 "预留预留";
CM_ SG_ 2332110495 M2I_Byrack_IsPostTm_IMM14_15 "绝缘采样时间_IMM14";
CM_ SG_ 2332110495 M2I_Byrack_SysABStTm_IMM14_15 "电压稳定时间_IMM14";
CM_ SG_ 2332110496 CRC_M2I_Byrack_IMM14_16 "CRC校验_IMM14";
CM_ SG_ 2332110496 M2I_Byrack_HVS_IMM14_16 "绝缘测量电压_IMM14";
CM_ SG_ 2332110496 M2I_Byrack_Enable_IMM14_16 "绝缘采样使能位_IMM14";
CM_ SG_ 2332110496 M2I_Byrack_ReVeEnable_IMM14_16 "读取软件版本使能位_IMM14";
CM_ SG_ 2332110496 Reserved_16 "预留预留";
CM_ SG_ 2332110496 M2I_Byrack_IsPostTm_IMM14_16 "绝缘采样时间_IMM14";
CM_ SG_ 2332110496 M2I_Byrack_SysABStTm_IMM14_16 "电压稳定时间_IMM14";
CM_ SG_ 2332110497 CRC_M2I_Byrack_IMM14_17 "CRC校验_IMM14";
CM_ SG_ 2332110497 M2I_Byrack_HVS_IMM14_17 "绝缘测量电压_IMM14";
CM_ SG_ 2332110497 M2I_Byrack_Enable_IMM14_17 "绝缘采样使能位_IMM14";
CM_ SG_ 2332110497 M2I_Byrack_ReVeEnable_IMM14_17 "读取软件版本使能位_IMM14";
CM_ SG_ 2332110497 Reserved_17 "预留预留";
CM_ SG_ 2332110497 M2I_Byrack_IsPostTm_IMM14_17 "绝缘采样时间_IMM14";
CM_ SG_ 2332110497 M2I_Byrack_SysABStTm_IMM14_17 "电压稳定时间_IMM14";
CM_ SG_ 2332110498 CRC_M2I_Byrack_IMM14_18 "CRC校验_IMM14";
CM_ SG_ 2332110498 M2I_Byrack_HVS_IMM14_18 "绝缘测量电压_IMM14";
CM_ SG_ 2332110498 M2I_Byrack_Enable_IMM14_18 "绝缘采样使能位_IMM14";
CM_ SG_ 2332110498 M2I_Byrack_ReVeEnable_IMM14_18 "读取软件版本使能位_IMM14";
CM_ SG_ 2332110498 Reserved_18 "预留预留";
CM_ SG_ 2332110498 M2I_Byrack_IsPostTm_IMM14_18 "绝缘采样时间_IMM14";
CM_ SG_ 2332110498 M2I_Byrack_SysABStTm_IMM14_18 "电压稳定时间_IMM14";
CM_ SG_ 2332110499 CRC_M2I_Byrack_IMM14_19 "CRC校验_IMM14";
CM_ SG_ 2332110499 M2I_Byrack_HVS_IMM14_19 "绝缘测量电压_IMM14";
CM_ SG_ 2332110499 M2I_Byrack_Enable_IMM14_19 "绝缘采样使能位_IMM14";
CM_ SG_ 2332110499 M2I_Byrack_ReVeEnable_IMM14_19 "读取软件版本使能位_IMM14";
CM_ SG_ 2332110499 Reserved_19 "预留预留";
CM_ SG_ 2332110499 M2I_Byrack_IsPostTm_IMM14_19 "绝缘采样时间_IMM14";
CM_ SG_ 2332110499 M2I_Byrack_SysABStTm_IMM14_19 "电压稳定时间_IMM14";
CM_ SG_ 2332110500 CRC_M2I_Byrack_IMM14_20 "CRC校验_IMM14";
CM_ SG_ 2332110500 M2I_Byrack_HVS_IMM14_20 "绝缘测量电压_IMM14";
CM_ SG_ 2332110500 M2I_Byrack_Enable_IMM14_20 "绝缘采样使能位_IMM14";
CM_ SG_ 2332110500 M2I_Byrack_ReVeEnable_IMM14_20 "读取软件版本使能位_IMM14";
CM_ SG_ 2332110500 Reserved_20 "预留预留";
CM_ SG_ 2332110500 M2I_Byrack_IsPostTm_IMM14_20 "绝缘采样时间_IMM14";
CM_ SG_ 2332110500 M2I_Byrack_SysABStTm_IMM14_20 "电压稳定时间_IMM14";
CM_ SG_ 2332110501 CRC_M2I_Byrack_IMM14_21 "CRC校验_IMM14";
CM_ SG_ 2332110501 M2I_Byrack_HVS_IMM14_21 "绝缘测量电压_IMM14";
CM_ SG_ 2332110501 M2I_Byrack_Enable_IMM14_21 "绝缘采样使能位_IMM14";
CM_ SG_ 2332110501 M2I_Byrack_ReVeEnable_IMM14_21 "读取软件版本使能位_IMM14";
CM_ SG_ 2332110501 Reserved_21 "预留预留";
CM_ SG_ 2332110501 M2I_Byrack_IsPostTm_IMM14_21 "绝缘采样时间_IMM14";
CM_ SG_ 2332110501 M2I_Byrack_SysABStTm_IMM14_21 "电压稳定时间_IMM14";
CM_ SG_ 2332110502 CRC_M2I_Byrack_IMM14_22 "CRC校验_IMM14";
CM_ SG_ 2332110502 M2I_Byrack_HVS_IMM14_22 "绝缘测量电压_IMM14";
CM_ SG_ 2332110502 M2I_Byrack_Enable_IMM14_22 "绝缘采样使能位_IMM14";
CM_ SG_ 2332110502 M2I_Byrack_ReVeEnable_IMM14_22 "读取软件版本使能位_IMM14";
CM_ SG_ 2332110502 Reserved_22 "预留预留";
CM_ SG_ 2332110502 M2I_Byrack_IsPostTm_IMM14_22 "绝缘采样时间_IMM14";
CM_ SG_ 2332110502 M2I_Byrack_SysABStTm_IMM14_22 "电压稳定时间_IMM14";
CM_ SG_ 2332110503 CRC_M2I_Byrack_IMM14_23 "CRC校验_IMM14";
CM_ SG_ 2332110503 M2I_Byrack_HVS_IMM14_23 "绝缘测量电压_IMM14";
CM_ SG_ 2332110503 M2I_Byrack_Enable_IMM14_23 "绝缘采样使能位_IMM14";
CM_ SG_ 2332110503 M2I_Byrack_ReVeEnable_IMM14_23 "读取软件版本使能位_IMM14";
CM_ SG_ 2332110503 Reserved_23 "预留预留";
CM_ SG_ 2332110503 M2I_Byrack_IsPostTm_IMM14_23 "绝缘采样时间_IMM14";
CM_ SG_ 2332110503 M2I_Byrack_SysABStTm_IMM14_23 "电压稳定时间_IMM14";
CM_ SG_ 2332110504 CRC_M2I_Byrack_IMM14_24 "CRC校验_IMM14";
CM_ SG_ 2332110504 M2I_Byrack_HVS_IMM14_24 "绝缘测量电压_IMM14";
CM_ SG_ 2332110504 M2I_Byrack_Enable_IMM14_24 "绝缘采样使能位_IMM14";
CM_ SG_ 2332110504 M2I_Byrack_ReVeEnable_IMM14_24 "读取软件版本使能位_IMM14";
CM_ SG_ 2332110504 Reserved_24 "预留预留";
CM_ SG_ 2332110504 M2I_Byrack_IsPostTm_IMM14_24 "绝缘采样时间_IMM14";
CM_ SG_ 2332110504 M2I_Byrack_SysABStTm_IMM14_24 "电压稳定时间_IMM14";
CM_ SG_ 2332110505 CRC_M2I_Byrack_IMM14_25 "CRC校验_IMM14";
CM_ SG_ 2332110505 M2I_Byrack_HVS_IMM14_25 "绝缘测量电压_IMM14";
CM_ SG_ 2332110505 M2I_Byrack_Enable_IMM14_25 "绝缘采样使能位_IMM14";
CM_ SG_ 2332110505 M2I_Byrack_ReVeEnable_IMM14_25 "读取软件版本使能位_IMM14";
CM_ SG_ 2332110505 Reserved_25 "预留预留";
CM_ SG_ 2332110505 M2I_Byrack_IsPostTm_IMM14_25 "绝缘采样时间_IMM14";
CM_ SG_ 2332110505 M2I_Byrack_SysABStTm_IMM14_25 "电压稳定时间_IMM14";
CM_ SG_ 2332110506 CRC_M2I_Byrack_IMM14_26 "CRC校验_IMM14";
CM_ SG_ 2332110506 M2I_Byrack_HVS_IMM14_26 "绝缘测量电压_IMM14";
CM_ SG_ 2332110506 M2I_Byrack_Enable_IMM14_26 "绝缘采样使能位_IMM14";
CM_ SG_ 2332110506 M2I_Byrack_ReVeEnable_IMM14_26 "读取软件版本使能位_IMM14";
CM_ SG_ 2332110506 Reserved_26 "预留预留";
CM_ SG_ 2332110506 M2I_Byrack_IsPostTm_IMM14_26 "绝缘采样时间_IMM14";
CM_ SG_ 2332110506 M2I_Byrack_SysABStTm_IMM14_26 "电压稳定时间_IMM14";
CM_ SG_ 2332110507 CRC_M2I_Byrack_IMM14_27 "CRC校验_IMM14";
CM_ SG_ 2332110507 M2I_Byrack_HVS_IMM14_27 "绝缘测量电压_IMM14";
CM_ SG_ 2332110507 M2I_Byrack_Enable_IMM14_27 "绝缘采样使能位_IMM14";
CM_ SG_ 2332110507 M2I_Byrack_ReVeEnable_IMM14_27 "读取软件版本使能位_IMM14";
CM_ SG_ 2332110507 Reserved_27 "预留预留";
CM_ SG_ 2332110507 M2I_Byrack_IsPostTm_IMM14_27 "绝缘采样时间_IMM14";
CM_ SG_ 2332110507 M2I_Byrack_SysABStTm_IMM14_27 "电压稳定时间_IMM14";
CM_ SG_ 2332110508 CRC_M2I_Byrack_IMM14_28 "CRC校验_IMM14";
CM_ SG_ 2332110508 M2I_Byrack_HVS_IMM14_28 "绝缘测量电压_IMM14";
CM_ SG_ 2332110508 M2I_Byrack_Enable_IMM14_28 "绝缘采样使能位_IMM14";
CM_ SG_ 2332110508 M2I_Byrack_ReVeEnable_IMM14_28 "读取软件版本使能位_IMM14";
CM_ SG_ 2332110508 Reserved_28 "预留预留";
CM_ SG_ 2332110508 M2I_Byrack_IsPostTm_IMM14_28 "绝缘采样时间_IMM14";
CM_ SG_ 2332110508 M2I_Byrack_SysABStTm_IMM14_28 "电压稳定时间_IMM14";
CM_ SG_ 2332110509 CRC_M2I_Byrack_IMM14_29 "CRC校验_IMM14";
CM_ SG_ 2332110509 M2I_Byrack_HVS_IMM14_29 "绝缘测量电压_IMM14";
CM_ SG_ 2332110509 M2I_Byrack_Enable_IMM14_29 "绝缘采样使能位_IMM14";
CM_ SG_ 2332110509 M2I_Byrack_ReVeEnable_IMM14_29 "读取软件版本使能位_IMM14";
CM_ SG_ 2332110509 Reserved_29 "预留预留";
CM_ SG_ 2332110509 M2I_Byrack_IsPostTm_IMM14_29 "绝缘采样时间_IMM14";
CM_ SG_ 2332110509 M2I_Byrack_SysABStTm_IMM14_29 "电压稳定时间_IMM14";
CM_ SG_ 2332110510 CRC_M2I_Byrack_IMM14_30 "CRC校验_IMM14";
CM_ SG_ 2332110510 M2I_Byrack_HVS_IMM14_30 "绝缘测量电压_IMM14";
CM_ SG_ 2332110510 M2I_Byrack_Enable_IMM14_30 "绝缘采样使能位_IMM14";
CM_ SG_ 2332110510 M2I_Byrack_ReVeEnable_IMM14_30 "读取软件版本使能位_IMM14";
CM_ SG_ 2332110510 Reserved_30 "预留预留";
CM_ SG_ 2332110510 M2I_Byrack_IsPostTm_IMM14_30 "绝缘采样时间_IMM14";
CM_ SG_ 2332110510 M2I_Byrack_SysABStTm_IMM14_30 "电压稳定时间_IMM14";
CM_ SG_ 2332110511 CRC_M2I_Byrack_IMM14_31 "CRC校验_IMM14";
CM_ SG_ 2332110511 M2I_Byrack_HVS_IMM14_31 "绝缘测量电压_IMM14";
CM_ SG_ 2332110511 M2I_Byrack_Enable_IMM14_31 "绝缘采样使能位_IMM14";
CM_ SG_ 2332110511 M2I_Byrack_ReVeEnable_IMM14_31 "读取软件版本使能位_IMM14";
CM_ SG_ 2332110511 Reserved_31 "预留预留";
CM_ SG_ 2332110511 M2I_Byrack_IsPostTm_IMM14_31 "绝缘采样时间_IMM14";
CM_ SG_ 2332110511 M2I_Byrack_SysABStTm_IMM14_31 "电压稳定时间_IMM14";
CM_ SG_ 2332110737 CRC_M2I_Byrack_IMM15_01 "CRC校验_IMM15";
CM_ SG_ 2332110737 M2I_Byrack_HVS_IMM15_01 "绝缘测量电压_IMM15";
CM_ SG_ 2332110737 M2I_Byrack_Enable_IMM15_01 "绝缘采样使能位_IMM15";
CM_ SG_ 2332110737 M2I_Byrack_ReVeEnable_IMM15_01 "读取软件版本使能位_IMM15";
CM_ SG_ 2332110737 Reserved_01 "预留预留";
CM_ SG_ 2332110737 M2I_Byrack_IsPostTm_IMM15_01 "绝缘采样时间_IMM15";
CM_ SG_ 2332110737 M2I_Byrack_SysABStTm_IMM15_01 "电压稳定时间_IMM15";
CM_ SG_ 2332110738 CRC_M2I_Byrack_IMM15_02 "CRC校验_IMM15";
CM_ SG_ 2332110738 M2I_Byrack_HVS_IMM15_02 "绝缘测量电压_IMM15";
CM_ SG_ 2332110738 M2I_Byrack_Enable_IMM15_02 "绝缘采样使能位_IMM15";
CM_ SG_ 2332110738 M2I_Byrack_ReVeEnable_IMM15_02 "读取软件版本使能位_IMM15";
CM_ SG_ 2332110738 Reserved_02 "预留预留";
CM_ SG_ 2332110738 M2I_Byrack_IsPostTm_IMM15_02 "绝缘采样时间_IMM15";
CM_ SG_ 2332110738 M2I_Byrack_SysABStTm_IMM15_02 "电压稳定时间_IMM15";
CM_ SG_ 2332110739 CRC_M2I_Byrack_IMM15_03 "CRC校验_IMM15";
CM_ SG_ 2332110739 M2I_Byrack_HVS_IMM15_03 "绝缘测量电压_IMM15";
CM_ SG_ 2332110739 M2I_Byrack_Enable_IMM15_03 "绝缘采样使能位_IMM15";
CM_ SG_ 2332110739 M2I_Byrack_ReVeEnable_IMM15_03 "读取软件版本使能位_IMM15";
CM_ SG_ 2332110739 Reserved_03 "预留预留";
CM_ SG_ 2332110739 M2I_Byrack_IsPostTm_IMM15_03 "绝缘采样时间_IMM15";
CM_ SG_ 2332110739 M2I_Byrack_SysABStTm_IMM15_03 "电压稳定时间_IMM15";
CM_ SG_ 2332110740 CRC_M2I_Byrack_IMM15_04 "CRC校验_IMM15";
CM_ SG_ 2332110740 M2I_Byrack_HVS_IMM15_04 "绝缘测量电压_IMM15";
CM_ SG_ 2332110740 M2I_Byrack_Enable_IMM15_04 "绝缘采样使能位_IMM15";
CM_ SG_ 2332110740 M2I_Byrack_ReVeEnable_IMM15_04 "读取软件版本使能位_IMM15";
CM_ SG_ 2332110740 Reserved_04 "预留预留";
CM_ SG_ 2332110740 M2I_Byrack_IsPostTm_IMM15_04 "绝缘采样时间_IMM15";
CM_ SG_ 2332110740 M2I_Byrack_SysABStTm_IMM15_04 "电压稳定时间_IMM15";
CM_ SG_ 2332110741 CRC_M2I_Byrack_IMM15_05 "CRC校验_IMM15";
CM_ SG_ 2332110741 M2I_Byrack_HVS_IMM15_05 "绝缘测量电压_IMM15";
CM_ SG_ 2332110741 M2I_Byrack_Enable_IMM15_05 "绝缘采样使能位_IMM15";
CM_ SG_ 2332110741 M2I_Byrack_ReVeEnable_IMM15_05 "读取软件版本使能位_IMM15";
CM_ SG_ 2332110741 Reserved_05 "预留预留";
CM_ SG_ 2332110741 M2I_Byrack_IsPostTm_IMM15_05 "绝缘采样时间_IMM15";
CM_ SG_ 2332110741 M2I_Byrack_SysABStTm_IMM15_05 "电压稳定时间_IMM15";
CM_ SG_ 2332110742 CRC_M2I_Byrack_IMM15_06 "CRC校验_IMM15";
CM_ SG_ 2332110742 M2I_Byrack_HVS_IMM15_06 "绝缘测量电压_IMM15";
CM_ SG_ 2332110742 M2I_Byrack_Enable_IMM15_06 "绝缘采样使能位_IMM15";
CM_ SG_ 2332110742 M2I_Byrack_ReVeEnable_IMM15_06 "读取软件版本使能位_IMM15";
CM_ SG_ 2332110742 Reserved_06 "预留预留";
CM_ SG_ 2332110742 M2I_Byrack_IsPostTm_IMM15_06 "绝缘采样时间_IMM15";
CM_ SG_ 2332110742 M2I_Byrack_SysABStTm_IMM15_06 "电压稳定时间_IMM15";
CM_ SG_ 2332110743 CRC_M2I_Byrack_IMM15_07 "CRC校验_IMM15";
CM_ SG_ 2332110743 M2I_Byrack_HVS_IMM15_07 "绝缘测量电压_IMM15";
CM_ SG_ 2332110743 M2I_Byrack_Enable_IMM15_07 "绝缘采样使能位_IMM15";
CM_ SG_ 2332110743 M2I_Byrack_ReVeEnable_IMM15_07 "读取软件版本使能位_IMM15";
CM_ SG_ 2332110743 Reserved_07 "预留预留";
CM_ SG_ 2332110743 M2I_Byrack_IsPostTm_IMM15_07 "绝缘采样时间_IMM15";
CM_ SG_ 2332110743 M2I_Byrack_SysABStTm_IMM15_07 "电压稳定时间_IMM15";
CM_ SG_ 2332110744 CRC_M2I_Byrack_IMM15_08 "CRC校验_IMM15";
CM_ SG_ 2332110744 M2I_Byrack_HVS_IMM15_08 "绝缘测量电压_IMM15";
CM_ SG_ 2332110744 M2I_Byrack_Enable_IMM15_08 "绝缘采样使能位_IMM15";
CM_ SG_ 2332110744 M2I_Byrack_ReVeEnable_IMM15_08 "读取软件版本使能位_IMM15";
CM_ SG_ 2332110744 Reserved_08 "预留预留";
CM_ SG_ 2332110744 M2I_Byrack_IsPostTm_IMM15_08 "绝缘采样时间_IMM15";
CM_ SG_ 2332110744 M2I_Byrack_SysABStTm_IMM15_08 "电压稳定时间_IMM15";
CM_ SG_ 2332110745 CRC_M2I_Byrack_IMM15_09 "CRC校验_IMM15";
CM_ SG_ 2332110745 M2I_Byrack_HVS_IMM15_09 "绝缘测量电压_IMM15";
CM_ SG_ 2332110745 M2I_Byrack_Enable_IMM15_09 "绝缘采样使能位_IMM15";
CM_ SG_ 2332110745 M2I_Byrack_ReVeEnable_IMM15_09 "读取软件版本使能位_IMM15";
CM_ SG_ 2332110745 Reserved_09 "预留预留";
CM_ SG_ 2332110745 M2I_Byrack_IsPostTm_IMM15_09 "绝缘采样时间_IMM15";
CM_ SG_ 2332110745 M2I_Byrack_SysABStTm_IMM15_09 "电压稳定时间_IMM15";
CM_ SG_ 2332110746 CRC_M2I_Byrack_IMM15_10 "CRC校验_IMM15";
CM_ SG_ 2332110746 M2I_Byrack_HVS_IMM15_10 "绝缘测量电压_IMM15";
CM_ SG_ 2332110746 M2I_Byrack_Enable_IMM15_10 "绝缘采样使能位_IMM15";
CM_ SG_ 2332110746 M2I_Byrack_ReVeEnable_IMM15_10 "读取软件版本使能位_IMM15";
CM_ SG_ 2332110746 Reserved_10 "预留预留";
CM_ SG_ 2332110746 M2I_Byrack_IsPostTm_IMM15_10 "绝缘采样时间_IMM15";
CM_ SG_ 2332110746 M2I_Byrack_SysABStTm_IMM15_10 "电压稳定时间_IMM15";
CM_ SG_ 2332110747 CRC_M2I_Byrack_IMM15_11 "CRC校验_IMM15";
CM_ SG_ 2332110747 M2I_Byrack_HVS_IMM15_11 "绝缘测量电压_IMM15";
CM_ SG_ 2332110747 M2I_Byrack_Enable_IMM15_11 "绝缘采样使能位_IMM15";
CM_ SG_ 2332110747 M2I_Byrack_ReVeEnable_IMM15_11 "读取软件版本使能位_IMM15";
CM_ SG_ 2332110747 Reserved_11 "预留预留";
CM_ SG_ 2332110747 M2I_Byrack_IsPostTm_IMM15_11 "绝缘采样时间_IMM15";
CM_ SG_ 2332110747 M2I_Byrack_SysABStTm_IMM15_11 "电压稳定时间_IMM15";
CM_ SG_ 2332110748 CRC_M2I_Byrack_IMM15_12 "CRC校验_IMM15";
CM_ SG_ 2332110748 M2I_Byrack_HVS_IMM15_12 "绝缘测量电压_IMM15";
CM_ SG_ 2332110748 M2I_Byrack_Enable_IMM15_12 "绝缘采样使能位_IMM15";
CM_ SG_ 2332110748 M2I_Byrack_ReVeEnable_IMM15_12 "读取软件版本使能位_IMM15";
CM_ SG_ 2332110748 Reserved_12 "预留预留";
CM_ SG_ 2332110748 M2I_Byrack_IsPostTm_IMM15_12 "绝缘采样时间_IMM15";
CM_ SG_ 2332110748 M2I_Byrack_SysABStTm_IMM15_12 "电压稳定时间_IMM15";
CM_ SG_ 2332110749 CRC_M2I_Byrack_IMM15_13 "CRC校验_IMM15";
CM_ SG_ 2332110749 M2I_Byrack_HVS_IMM15_13 "绝缘测量电压_IMM15";
CM_ SG_ 2332110749 M2I_Byrack_Enable_IMM15_13 "绝缘采样使能位_IMM15";
CM_ SG_ 2332110749 M2I_Byrack_ReVeEnable_IMM15_13 "读取软件版本使能位_IMM15";
CM_ SG_ 2332110749 Reserved_13 "预留预留";
CM_ SG_ 2332110749 M2I_Byrack_IsPostTm_IMM15_13 "绝缘采样时间_IMM15";
CM_ SG_ 2332110749 M2I_Byrack_SysABStTm_IMM15_13 "电压稳定时间_IMM15";
CM_ SG_ 2332110750 CRC_M2I_Byrack_IMM15_14 "CRC校验_IMM15";
CM_ SG_ 2332110750 M2I_Byrack_HVS_IMM15_14 "绝缘测量电压_IMM15";
CM_ SG_ 2332110750 M2I_Byrack_Enable_IMM15_14 "绝缘采样使能位_IMM15";
CM_ SG_ 2332110750 M2I_Byrack_ReVeEnable_IMM15_14 "读取软件版本使能位_IMM15";
CM_ SG_ 2332110750 Reserved_14 "预留预留";
CM_ SG_ 2332110750 M2I_Byrack_IsPostTm_IMM15_14 "绝缘采样时间_IMM15";
CM_ SG_ 2332110750 M2I_Byrack_SysABStTm_IMM15_14 "电压稳定时间_IMM15";
CM_ SG_ 2332110751 CRC_M2I_Byrack_IMM15_15 "CRC校验_IMM15";
CM_ SG_ 2332110751 M2I_Byrack_HVS_IMM15_15 "绝缘测量电压_IMM15";
CM_ SG_ 2332110751 M2I_Byrack_Enable_IMM15_15 "绝缘采样使能位_IMM15";
CM_ SG_ 2332110751 M2I_Byrack_ReVeEnable_IMM15_15 "读取软件版本使能位_IMM15";
CM_ SG_ 2332110751 Reserved_15 "预留预留";
CM_ SG_ 2332110751 M2I_Byrack_IsPostTm_IMM15_15 "绝缘采样时间_IMM15";
CM_ SG_ 2332110751 M2I_Byrack_SysABStTm_IMM15_15 "电压稳定时间_IMM15";
CM_ SG_ 2332110752 CRC_M2I_Byrack_IMM15_16 "CRC校验_IMM15";
CM_ SG_ 2332110752 M2I_Byrack_HVS_IMM15_16 "绝缘测量电压_IMM15";
CM_ SG_ 2332110752 M2I_Byrack_Enable_IMM15_16 "绝缘采样使能位_IMM15";
CM_ SG_ 2332110752 M2I_Byrack_ReVeEnable_IMM15_16 "读取软件版本使能位_IMM15";
CM_ SG_ 2332110752 Reserved_16 "预留预留";
CM_ SG_ 2332110752 M2I_Byrack_IsPostTm_IMM15_16 "绝缘采样时间_IMM15";
CM_ SG_ 2332110752 M2I_Byrack_SysABStTm_IMM15_16 "电压稳定时间_IMM15";
CM_ SG_ 2332110753 CRC_M2I_Byrack_IMM15_17 "CRC校验_IMM15";
CM_ SG_ 2332110753 M2I_Byrack_HVS_IMM15_17 "绝缘测量电压_IMM15";
CM_ SG_ 2332110753 M2I_Byrack_Enable_IMM15_17 "绝缘采样使能位_IMM15";
CM_ SG_ 2332110753 M2I_Byrack_ReVeEnable_IMM15_17 "读取软件版本使能位_IMM15";
CM_ SG_ 2332110753 Reserved_17 "预留预留";
CM_ SG_ 2332110753 M2I_Byrack_IsPostTm_IMM15_17 "绝缘采样时间_IMM15";
CM_ SG_ 2332110753 M2I_Byrack_SysABStTm_IMM15_17 "电压稳定时间_IMM15";
CM_ SG_ 2332110754 CRC_M2I_Byrack_IMM15_18 "CRC校验_IMM15";
CM_ SG_ 2332110754 M2I_Byrack_HVS_IMM15_18 "绝缘测量电压_IMM15";
CM_ SG_ 2332110754 M2I_Byrack_Enable_IMM15_18 "绝缘采样使能位_IMM15";
CM_ SG_ 2332110754 M2I_Byrack_ReVeEnable_IMM15_18 "读取软件版本使能位_IMM15";
CM_ SG_ 2332110754 Reserved_18 "预留预留";
CM_ SG_ 2332110754 M2I_Byrack_IsPostTm_IMM15_18 "绝缘采样时间_IMM15";
CM_ SG_ 2332110754 M2I_Byrack_SysABStTm_IMM15_18 "电压稳定时间_IMM15";
CM_ SG_ 2332110755 CRC_M2I_Byrack_IMM15_19 "CRC校验_IMM15";
CM_ SG_ 2332110755 M2I_Byrack_HVS_IMM15_19 "绝缘测量电压_IMM15";
CM_ SG_ 2332110755 M2I_Byrack_Enable_IMM15_19 "绝缘采样使能位_IMM15";
CM_ SG_ 2332110755 M2I_Byrack_ReVeEnable_IMM15_19 "读取软件版本使能位_IMM15";
CM_ SG_ 2332110755 Reserved_19 "预留预留";
CM_ SG_ 2332110755 M2I_Byrack_IsPostTm_IMM15_19 "绝缘采样时间_IMM15";
CM_ SG_ 2332110755 M2I_Byrack_SysABStTm_IMM15_19 "电压稳定时间_IMM15";
CM_ SG_ 2332110756 CRC_M2I_Byrack_IMM15_20 "CRC校验_IMM15";
CM_ SG_ 2332110756 M2I_Byrack_HVS_IMM15_20 "绝缘测量电压_IMM15";
CM_ SG_ 2332110756 M2I_Byrack_Enable_IMM15_20 "绝缘采样使能位_IMM15";
CM_ SG_ 2332110756 M2I_Byrack_ReVeEnable_IMM15_20 "读取软件版本使能位_IMM15";
CM_ SG_ 2332110756 Reserved_20 "预留预留";
CM_ SG_ 2332110756 M2I_Byrack_IsPostTm_IMM15_20 "绝缘采样时间_IMM15";
CM_ SG_ 2332110756 M2I_Byrack_SysABStTm_IMM15_20 "电压稳定时间_IMM15";
CM_ SG_ 2332110757 CRC_M2I_Byrack_IMM15_21 "CRC校验_IMM15";
CM_ SG_ 2332110757 M2I_Byrack_HVS_IMM15_21 "绝缘测量电压_IMM15";
CM_ SG_ 2332110757 M2I_Byrack_Enable_IMM15_21 "绝缘采样使能位_IMM15";
CM_ SG_ 2332110757 M2I_Byrack_ReVeEnable_IMM15_21 "读取软件版本使能位_IMM15";
CM_ SG_ 2332110757 Reserved_21 "预留预留";
CM_ SG_ 2332110757 M2I_Byrack_IsPostTm_IMM15_21 "绝缘采样时间_IMM15";
CM_ SG_ 2332110757 M2I_Byrack_SysABStTm_IMM15_21 "电压稳定时间_IMM15";
CM_ SG_ 2332110758 CRC_M2I_Byrack_IMM15_22 "CRC校验_IMM15";
CM_ SG_ 2332110758 M2I_Byrack_HVS_IMM15_22 "绝缘测量电压_IMM15";
CM_ SG_ 2332110758 M2I_Byrack_Enable_IMM15_22 "绝缘采样使能位_IMM15";
CM_ SG_ 2332110758 M2I_Byrack_ReVeEnable_IMM15_22 "读取软件版本使能位_IMM15";
CM_ SG_ 2332110758 Reserved_22 "预留预留";
CM_ SG_ 2332110758 M2I_Byrack_IsPostTm_IMM15_22 "绝缘采样时间_IMM15";
CM_ SG_ 2332110758 M2I_Byrack_SysABStTm_IMM15_22 "电压稳定时间_IMM15";
CM_ SG_ 2332110759 CRC_M2I_Byrack_IMM15_23 "CRC校验_IMM15";
CM_ SG_ 2332110759 M2I_Byrack_HVS_IMM15_23 "绝缘测量电压_IMM15";
CM_ SG_ 2332110759 M2I_Byrack_Enable_IMM15_23 "绝缘采样使能位_IMM15";
CM_ SG_ 2332110759 M2I_Byrack_ReVeEnable_IMM15_23 "读取软件版本使能位_IMM15";
CM_ SG_ 2332110759 Reserved_23 "预留预留";
CM_ SG_ 2332110759 M2I_Byrack_IsPostTm_IMM15_23 "绝缘采样时间_IMM15";
CM_ SG_ 2332110759 M2I_Byrack_SysABStTm_IMM15_23 "电压稳定时间_IMM15";
CM_ SG_ 2332110760 CRC_M2I_Byrack_IMM15_24 "CRC校验_IMM15";
CM_ SG_ 2332110760 M2I_Byrack_HVS_IMM15_24 "绝缘测量电压_IMM15";
CM_ SG_ 2332110760 M2I_Byrack_Enable_IMM15_24 "绝缘采样使能位_IMM15";
CM_ SG_ 2332110760 M2I_Byrack_ReVeEnable_IMM15_24 "读取软件版本使能位_IMM15";
CM_ SG_ 2332110760 Reserved_24 "预留预留";
CM_ SG_ 2332110760 M2I_Byrack_IsPostTm_IMM15_24 "绝缘采样时间_IMM15";
CM_ SG_ 2332110760 M2I_Byrack_SysABStTm_IMM15_24 "电压稳定时间_IMM15";
CM_ SG_ 2332110761 CRC_M2I_Byrack_IMM15_25 "CRC校验_IMM15";
CM_ SG_ 2332110761 M2I_Byrack_HVS_IMM15_25 "绝缘测量电压_IMM15";
CM_ SG_ 2332110761 M2I_Byrack_Enable_IMM15_25 "绝缘采样使能位_IMM15";
CM_ SG_ 2332110761 M2I_Byrack_ReVeEnable_IMM15_25 "读取软件版本使能位_IMM15";
CM_ SG_ 2332110761 Reserved_25 "预留预留";
CM_ SG_ 2332110761 M2I_Byrack_IsPostTm_IMM15_25 "绝缘采样时间_IMM15";
CM_ SG_ 2332110761 M2I_Byrack_SysABStTm_IMM15_25 "电压稳定时间_IMM15";
CM_ SG_ 2332110762 CRC_M2I_Byrack_IMM15_26 "CRC校验_IMM15";
CM_ SG_ 2332110762 M2I_Byrack_HVS_IMM15_26 "绝缘测量电压_IMM15";
CM_ SG_ 2332110762 M2I_Byrack_Enable_IMM15_26 "绝缘采样使能位_IMM15";
CM_ SG_ 2332110762 M2I_Byrack_ReVeEnable_IMM15_26 "读取软件版本使能位_IMM15";
CM_ SG_ 2332110762 Reserved_26 "预留预留";
CM_ SG_ 2332110762 M2I_Byrack_IsPostTm_IMM15_26 "绝缘采样时间_IMM15";
CM_ SG_ 2332110762 M2I_Byrack_SysABStTm_IMM15_26 "电压稳定时间_IMM15";
CM_ SG_ 2332110763 CRC_M2I_Byrack_IMM15_27 "CRC校验_IMM15";
CM_ SG_ 2332110763 M2I_Byrack_HVS_IMM15_27 "绝缘测量电压_IMM15";
CM_ SG_ 2332110763 M2I_Byrack_Enable_IMM15_27 "绝缘采样使能位_IMM15";
CM_ SG_ 2332110763 M2I_Byrack_ReVeEnable_IMM15_27 "读取软件版本使能位_IMM15";
CM_ SG_ 2332110763 Reserved_27 "预留预留";
CM_ SG_ 2332110763 M2I_Byrack_IsPostTm_IMM15_27 "绝缘采样时间_IMM15";
CM_ SG_ 2332110763 M2I_Byrack_SysABStTm_IMM15_27 "电压稳定时间_IMM15";
CM_ SG_ 2332110764 CRC_M2I_Byrack_IMM15_28 "CRC校验_IMM15";
CM_ SG_ 2332110764 M2I_Byrack_HVS_IMM15_28 "绝缘测量电压_IMM15";
CM_ SG_ 2332110764 M2I_Byrack_Enable_IMM15_28 "绝缘采样使能位_IMM15";
CM_ SG_ 2332110764 M2I_Byrack_ReVeEnable_IMM15_28 "读取软件版本使能位_IMM15";
CM_ SG_ 2332110764 Reserved_28 "预留预留";
CM_ SG_ 2332110764 M2I_Byrack_IsPostTm_IMM15_28 "绝缘采样时间_IMM15";
CM_ SG_ 2332110764 M2I_Byrack_SysABStTm_IMM15_28 "电压稳定时间_IMM15";
CM_ SG_ 2332110765 CRC_M2I_Byrack_IMM15_29 "CRC校验_IMM15";
CM_ SG_ 2332110765 M2I_Byrack_HVS_IMM15_29 "绝缘测量电压_IMM15";
CM_ SG_ 2332110765 M2I_Byrack_Enable_IMM15_29 "绝缘采样使能位_IMM15";
CM_ SG_ 2332110765 M2I_Byrack_ReVeEnable_IMM15_29 "读取软件版本使能位_IMM15";
CM_ SG_ 2332110765 Reserved_29 "预留预留";
CM_ SG_ 2332110765 M2I_Byrack_IsPostTm_IMM15_29 "绝缘采样时间_IMM15";
CM_ SG_ 2332110765 M2I_Byrack_SysABStTm_IMM15_29 "电压稳定时间_IMM15";
CM_ SG_ 2332110766 CRC_M2I_Byrack_IMM15_30 "CRC校验_IMM15";
CM_ SG_ 2332110766 M2I_Byrack_HVS_IMM15_30 "绝缘测量电压_IMM15";
CM_ SG_ 2332110766 M2I_Byrack_Enable_IMM15_30 "绝缘采样使能位_IMM15";
CM_ SG_ 2332110766 M2I_Byrack_ReVeEnable_IMM15_30 "读取软件版本使能位_IMM15";
CM_ SG_ 2332110766 Reserved_30 "预留预留";
CM_ SG_ 2332110766 M2I_Byrack_IsPostTm_IMM15_30 "绝缘采样时间_IMM15";
CM_ SG_ 2332110766 M2I_Byrack_SysABStTm_IMM15_30 "电压稳定时间_IMM15";
CM_ SG_ 2332110767 CRC_M2I_Byrack_IMM15_31 "CRC校验_IMM15";
CM_ SG_ 2332110767 M2I_Byrack_HVS_IMM15_31 "绝缘测量电压_IMM15";
CM_ SG_ 2332110767 M2I_Byrack_Enable_IMM15_31 "绝缘采样使能位_IMM15";
CM_ SG_ 2332110767 M2I_Byrack_ReVeEnable_IMM15_31 "读取软件版本使能位_IMM15";
CM_ SG_ 2332110767 Reserved_31 "预留预留";
CM_ SG_ 2332110767 M2I_Byrack_IsPostTm_IMM15_31 "绝缘采样时间_IMM15";
CM_ SG_ 2332110767 M2I_Byrack_SysABStTm_IMM15_31 "电压稳定时间_IMM15";
CM_ SG_ 2332110993 CRC_M2I_Byrack_IMM16_01 "CRC校验_IMM16";
CM_ SG_ 2332110993 M2I_Byrack_HVS_IMM16_01 "绝缘测量电压_IMM16";
CM_ SG_ 2332110993 M2I_Byrack_Enable_IMM16_01 "绝缘采样使能位_IMM16";
CM_ SG_ 2332110993 M2I_Byrack_ReVeEnable_IMM16_01 "读取软件版本使能位_IMM16";
CM_ SG_ 2332110993 Reserved_01 "预留预留";
CM_ SG_ 2332110993 M2I_Byrack_IsPostTm_IMM16_01 "绝缘采样时间_IMM16";
CM_ SG_ 2332110993 M2I_Byrack_SysABStTm_IMM16_01 "电压稳定时间_IMM16";
CM_ SG_ 2332110994 CRC_M2I_Byrack_IMM16_02 "CRC校验_IMM16";
CM_ SG_ 2332110994 M2I_Byrack_HVS_IMM16_02 "绝缘测量电压_IMM16";
CM_ SG_ 2332110994 M2I_Byrack_Enable_IMM16_02 "绝缘采样使能位_IMM16";
CM_ SG_ 2332110994 M2I_Byrack_ReVeEnable_IMM16_02 "读取软件版本使能位_IMM16";
CM_ SG_ 2332110994 Reserved_02 "预留预留";
CM_ SG_ 2332110994 M2I_Byrack_IsPostTm_IMM16_02 "绝缘采样时间_IMM16";
CM_ SG_ 2332110994 M2I_Byrack_SysABStTm_IMM16_02 "电压稳定时间_IMM16";
CM_ SG_ 2332110995 CRC_M2I_Byrack_IMM16_03 "CRC校验_IMM16";
CM_ SG_ 2332110995 M2I_Byrack_HVS_IMM16_03 "绝缘测量电压_IMM16";
CM_ SG_ 2332110995 M2I_Byrack_Enable_IMM16_03 "绝缘采样使能位_IMM16";
CM_ SG_ 2332110995 M2I_Byrack_ReVeEnable_IMM16_03 "读取软件版本使能位_IMM16";
CM_ SG_ 2332110995 Reserved_03 "预留预留";
CM_ SG_ 2332110995 M2I_Byrack_IsPostTm_IMM16_03 "绝缘采样时间_IMM16";
CM_ SG_ 2332110995 M2I_Byrack_SysABStTm_IMM16_03 "电压稳定时间_IMM16";
CM_ SG_ 2332110996 CRC_M2I_Byrack_IMM16_04 "CRC校验_IMM16";
CM_ SG_ 2332110996 M2I_Byrack_HVS_IMM16_04 "绝缘测量电压_IMM16";
CM_ SG_ 2332110996 M2I_Byrack_Enable_IMM16_04 "绝缘采样使能位_IMM16";
CM_ SG_ 2332110996 M2I_Byrack_ReVeEnable_IMM16_04 "读取软件版本使能位_IMM16";
CM_ SG_ 2332110996 Reserved_04 "预留预留";
CM_ SG_ 2332110996 M2I_Byrack_IsPostTm_IMM16_04 "绝缘采样时间_IMM16";
CM_ SG_ 2332110996 M2I_Byrack_SysABStTm_IMM16_04 "电压稳定时间_IMM16";
CM_ SG_ 2332110997 CRC_M2I_Byrack_IMM16_05 "CRC校验_IMM16";
CM_ SG_ 2332110997 M2I_Byrack_HVS_IMM16_05 "绝缘测量电压_IMM16";
CM_ SG_ 2332110997 M2I_Byrack_Enable_IMM16_05 "绝缘采样使能位_IMM16";
CM_ SG_ 2332110997 M2I_Byrack_ReVeEnable_IMM16_05 "读取软件版本使能位_IMM16";
CM_ SG_ 2332110997 Reserved_05 "预留预留";
CM_ SG_ 2332110997 M2I_Byrack_IsPostTm_IMM16_05 "绝缘采样时间_IMM16";
CM_ SG_ 2332110997 M2I_Byrack_SysABStTm_IMM16_05 "电压稳定时间_IMM16";
CM_ SG_ 2332110998 CRC_M2I_Byrack_IMM16_06 "CRC校验_IMM16";
CM_ SG_ 2332110998 M2I_Byrack_HVS_IMM16_06 "绝缘测量电压_IMM16";
CM_ SG_ 2332110998 M2I_Byrack_Enable_IMM16_06 "绝缘采样使能位_IMM16";
CM_ SG_ 2332110998 M2I_Byrack_ReVeEnable_IMM16_06 "读取软件版本使能位_IMM16";
CM_ SG_ 2332110998 Reserved_06 "预留预留";
CM_ SG_ 2332110998 M2I_Byrack_IsPostTm_IMM16_06 "绝缘采样时间_IMM16";
CM_ SG_ 2332110998 M2I_Byrack_SysABStTm_IMM16_06 "电压稳定时间_IMM16";
VAL_ 2332109484 M2I_Byrack_Enable_IMM10_28 1 "Deactive" 2 "Active" ;
VAL_ 2332109484 M2I_Byrack_ReVeEnable_IMM10_28 0 "invalid" 1 "Read SW-Version" 2 "Read HW-Version" 3 "Barcode" ;
VAL_ 2332109485 M2I_Byrack_Enable_IMM10_29 1 "Deactive" 2 "Active" ;
VAL_ 2332109485 M2I_Byrack_ReVeEnable_IMM10_29 0 "invalid" 1 "Read SW-Version" 2 "Read HW-Version" 3 "Barcode" ;
VAL_ 2332109486 M2I_Byrack_Enable_IMM10_30 1 "Deactive" 2 "Active" ;
VAL_ 2332109486 M2I_Byrack_ReVeEnable_IMM10_30 0 "invalid" 1 "Read SW-Version" 2 "Read HW-Version" 3 "Barcode" ;
VAL_ 2332109487 M2I_Byrack_Enable_IMM10_31 1 "Deactive" 2 "Active" ;
VAL_ 2332109487 M2I_Byrack_ReVeEnable_IMM10_31 0 "invalid" 1 "Read SW-Version" 2 "Read HW-Version" 3 "Barcode" ;
VAL_ 2332109713 M2I_Byrack_Enable_IMM11_01 1 "Deactive" 2 "Active" ;
VAL_ 2332109713 M2I_Byrack_ReVeEnable_IMM11_01 0 "invalid" 1 "Read SW-Version" 2 "Read HW-Version" 3 "Barcode" ;
VAL_ 2332109714 M2I_Byrack_Enable_IMM11_02 1 "Deactive" 2 "Active" ;
VAL_ 2332109714 M2I_Byrack_ReVeEnable_IMM11_02 0 "invalid" 1 "Read SW-Version" 2 "Read HW-Version" 3 "Barcode" ;
VAL_ 2332109715 M2I_Byrack_Enable_IMM11_03 1 "Deactive" 2 "Active" ;
VAL_ 2332109715 M2I_Byrack_ReVeEnable_IMM11_03 0 "invalid" 1 "Read SW-Version" 2 "Read HW-Version" 3 "Barcode" ;
VAL_ 2332109716 M2I_Byrack_Enable_IMM11_04 1 "Deactive" 2 "Active" ;
VAL_ 2332109716 M2I_Byrack_ReVeEnable_IMM11_04 0 "invalid" 1 "Read SW-Version" 2 "Read HW-Version" 3 "Barcode" ;
VAL_ 2332109717 M2I_Byrack_Enable_IMM11_05 1 "Deactive" 2 "Active" ;
VAL_ 2332109717 M2I_Byrack_ReVeEnable_IMM11_05 0 "invalid" 1 "Read SW-Version" 2 "Read HW-Version" 3 "Barcode" ;
VAL_ 2332109718 M2I_Byrack_Enable_IMM11_06 1 "Deactive" 2 "Active" ;
VAL_ 2332109718 M2I_Byrack_ReVeEnable_IMM11_06 0 "invalid" 1 "Read SW-Version" 2 "Read HW-Version" 3 "Barcode" ;
VAL_ 2332109719 M2I_Byrack_Enable_IMM11_07 1 "Deactive" 2 "Active" ;
VAL_ 2332109719 M2I_Byrack_ReVeEnable_IMM11_07 0 "invalid" 1 "Read SW-Version" 2 "Read HW-Version" 3 "Barcode" ;
VAL_ 2332109720 M2I_Byrack_Enable_IMM11_08 1 "Deactive" 2 "Active" ;
VAL_ 2332109720 M2I_Byrack_ReVeEnable_IMM11_08 0 "invalid" 1 "Read SW-Version" 2 "Read HW-Version" 3 "Barcode" ;
VAL_ 2332109721 M2I_Byrack_Enable_IMM11_09 1 "Deactive" 2 "Active" ;
VAL_ 2332109721 M2I_Byrack_ReVeEnable_IMM11_09 0 "invalid" 1 "Read SW-Version" 2 "Read HW-Version" 3 "Barcode" ;
VAL_ 2332109722 M2I_Byrack_Enable_IMM11_10 1 "Deactive" 2 "Active" ;
VAL_ 2332109722 M2I_Byrack_ReVeEnable_IMM11_10 0 "invalid" 1 "Read SW-Version" 2 "Read HW-Version" 3 "Barcode" ;
VAL_ 2332109723 M2I_Byrack_Enable_IMM11_11 1 "Deactive" 2 "Active" ;
VAL_ 2332109723 M2I_Byrack_ReVeEnable_IMM11_11 0 "invalid" 1 "Read SW-Version" 2 "Read HW-Version" 3 "Barcode" ;
VAL_ 2332109724 M2I_Byrack_Enable_IMM11_12 1 "Deactive" 2 "Active" ;
VAL_ 2332109724 M2I_Byrack_ReVeEnable_IMM11_12 0 "invalid" 1 "Read SW-Version" 2 "Read HW-Version" 3 "Barcode" ;
VAL_ 2332109725 M2I_Byrack_Enable_IMM11_13 1 "Deactive" 2 "Active" ;
VAL_ 2332109725 M2I_Byrack_ReVeEnable_IMM11_13 0 "invalid" 1 "Read SW-Version" 2 "Read HW-Version" 3 "Barcode" ;
VAL_ 2332109726 M2I_Byrack_Enable_IMM11_14 1 "Deactive" 2 "Active" ;
VAL_ 2332109726 M2I_Byrack_ReVeEnable_IMM11_14 0 "invalid" 1 "Read SW-Version" 2 "Read HW-Version" 3 "Barcode" ;
VAL_ 2332109727 M2I_Byrack_Enable_IMM11_15 1 "Deactive" 2 "Active" ;
VAL_ 2332109727 M2I_Byrack_ReVeEnable_IMM11_15 0 "invalid" 1 "Read SW-Version" 2 "Read HW-Version" 3 "Barcode" ;
VAL_ 2332109728 M2I_Byrack_Enable_IMM11_16 1 "Deactive" 2 "Active" ;
VAL_ 2332109728 M2I_Byrack_ReVeEnable_IMM11_16 0 "invalid" 1 "Read SW-Version" 2 "Read HW-Version" 3 "Barcode" ;
VAL_ 2332109729 M2I_Byrack_Enable_IMM11_17 1 "Deactive" 2 "Active" ;
VAL_ 2332109729 M2I_Byrack_ReVeEnable_IMM11_17 0 "invalid" 1 "Read SW-Version" 2 "Read HW-Version" 3 "Barcode" ;
VAL_ 2332109730 M2I_Byrack_Enable_IMM11_18 1 "Deactive" 2 "Active" ;
VAL_ 2332109730 M2I_Byrack_ReVeEnable_IMM11_18 0 "invalid" 1 "Read SW-Version" 2 "Read HW-Version" 3 "Barcode" ;
VAL_ 2332109731 M2I_Byrack_Enable_IMM11_19 1 "Deactive" 2 "Active" ;
VAL_ 2332109731 M2I_Byrack_ReVeEnable_IMM11_19 0 "invalid" 1 "Read SW-Version" 2 "Read HW-Version" 3 "Barcode" ;
VAL_ 2332109732 M2I_Byrack_Enable_IMM11_20 1 "Deactive" 2 "Active" ;
VAL_ 2332109732 M2I_Byrack_ReVeEnable_IMM11_20 0 "invalid" 1 "Read SW-Version" 2 "Read HW-Version" 3 "Barcode" ;
VAL_ 2332109733 M2I_Byrack_Enable_IMM11_21 1 "Deactive" 2 "Active" ;
VAL_ 2332109733 M2I_Byrack_ReVeEnable_IMM11_21 0 "invalid" 1 "Read SW-Version" 2 "Read HW-Version" 3 "Barcode" ;
VAL_ 2332109734 M2I_Byrack_Enable_IMM11_22 1 "Deactive" 2 "Active" ;
VAL_ 2332109734 M2I_Byrack_ReVeEnable_IMM11_22 0 "invalid" 1 "Read SW-Version" 2 "Read HW-Version" 3 "Barcode" ;
VAL_ 2332109735 M2I_Byrack_Enable_IMM11_23 1 "Deactive" 2 "Active" ;
VAL_ 2332109735 M2I_Byrack_ReVeEnable_IMM11_23 0 "invalid" 1 "Read SW-Version" 2 "Read HW-Version" 3 "Barcode" ;
VAL_ 2332109736 M2I_Byrack_Enable_IMM11_24 1 "Deactive" 2 "Active" ;
VAL_ 2332109736 M2I_Byrack_ReVeEnable_IMM11_24 0 "invalid" 1 "Read SW-Version" 2 "Read HW-Version" 3 "Barcode" ;
VAL_ 2332109737 M2I_Byrack_Enable_IMM11_25 1 "Deactive" 2 "Active" ;
VAL_ 2332109737 M2I_Byrack_ReVeEnable_IMM11_25 0 "invalid" 1 "Read SW-Version" 2 "Read HW-Version" 3 "Barcode" ;
VAL_ 2332109738 M2I_Byrack_Enable_IMM11_26 1 "Deactive" 2 "Active" ;
VAL_ 2332109738 M2I_Byrack_ReVeEnable_IMM11_26 0 "invalid" 1 "Read SW-Version" 2 "Read HW-Version" 3 "Barcode" ;
VAL_ 2332109739 M2I_Byrack_Enable_IMM11_27 1 "Deactive" 2 "Active" ;
VAL_ 2332109739 M2I_Byrack_ReVeEnable_IMM11_27 0 "invalid" 1 "Read SW-Version" 2 "Read HW-Version" 3 "Barcode" ;
VAL_ 2332109740 M2I_Byrack_Enable_IMM11_28 1 "Deactive" 2 "Active" ;
VAL_ 2332109740 M2I_Byrack_ReVeEnable_IMM11_28 0 "invalid" 1 "Read SW-Version" 2 "Read HW-Version" 3 "Barcode" ;
VAL_ 2332109741 M2I_Byrack_Enable_IMM11_29 1 "Deactive" 2 "Active" ;
VAL_ 2332109741 M2I_Byrack_ReVeEnable_IMM11_29 0 "invalid" 1 "Read SW-Version" 2 "Read HW-Version" 3 "Barcode" ;
VAL_ 2332109742 M2I_Byrack_Enable_IMM11_30 1 "Deactive" 2 "Active" ;
VAL_ 2332109742 M2I_Byrack_ReVeEnable_IMM11_30 0 "invalid" 1 "Read SW-Version" 2 "Read HW-Version" 3 "Barcode" ;
VAL_ 2332109743 M2I_Byrack_Enable_IMM11_31 1 "Deactive" 2 "Active" ;
VAL_ 2332109743 M2I_Byrack_ReVeEnable_IMM11_31 0 "invalid" 1 "Read SW-Version" 2 "Read HW-Version" 3 "Barcode" ;
VAL_ 2332109969 M2I_Byrack_Enable_IMM12_01 1 "Deactive" 2 "Active" ;
VAL_ 2332109969 M2I_Byrack_ReVeEnable_IMM12_01 0 "invalid" 1 "Read SW-Version" 2 "Read HW-Version" 3 "Barcode" ;
VAL_ 2332109970 M2I_Byrack_Enable_IMM12_02 1 "Deactive" 2 "Active" ;
VAL_ 2332109970 M2I_Byrack_ReVeEnable_IMM12_02 0 "invalid" 1 "Read SW-Version" 2 "Read HW-Version" 3 "Barcode" ;
VAL_ 2332109971 M2I_Byrack_Enable_IMM12_03 1 "Deactive" 2 "Active" ;
VAL_ 2332109971 M2I_Byrack_ReVeEnable_IMM12_03 0 "invalid" 1 "Read SW-Version" 2 "Read HW-Version" 3 "Barcode" ;
VAL_ 2332109972 M2I_Byrack_Enable_IMM12_04 1 "Deactive" 2 "Active" ;
VAL_ 2332109972 M2I_Byrack_ReVeEnable_IMM12_04 0 "invalid" 1 "Read SW-Version" 2 "Read HW-Version" 3 "Barcode" ;
VAL_ 2332109973 M2I_Byrack_Enable_IMM12_05 1 "Deactive" 2 "Active" ;
VAL_ 2332109973 M2I_Byrack_ReVeEnable_IMM12_05 0 "invalid" 1 "Read SW-Version" 2 "Read HW-Version" 3 "Barcode" ;
VAL_ 2332109974 M2I_Byrack_Enable_IMM12_06 1 "Deactive" 2 "Active" ;
VAL_ 2332109974 M2I_Byrack_ReVeEnable_IMM12_06 0 "invalid" 1 "Read SW-Version" 2 "Read HW-Version" 3 "Barcode" ;
VAL_ 2332109975 M2I_Byrack_Enable_IMM12_07 1 "Deactive" 2 "Active" ;
VAL_ 2332109975 M2I_Byrack_ReVeEnable_IMM12_07 0 "invalid" 1 "Read SW-Version" 2 "Read HW-Version" 3 "Barcode" ;
VAL_ 2332109976 M2I_Byrack_Enable_IMM12_08 1 "Deactive" 2 "Active" ;
VAL_ 2332109976 M2I_Byrack_ReVeEnable_IMM12_08 0 "invalid" 1 "Read SW-Version" 2 "Read HW-Version" 3 "Barcode" ;
VAL_ 2332109977 M2I_Byrack_Enable_IMM12_09 1 "Deactive" 2 "Active" ;
VAL_ 2332109977 M2I_Byrack_ReVeEnable_IMM12_09 0 "invalid" 1 "Read SW-Version" 2 "Read HW-Version" 3 "Barcode" ;
VAL_ 2332109978 M2I_Byrack_Enable_IMM12_10 1 "Deactive" 2 "Active" ;
VAL_ 2332109978 M2I_Byrack_ReVeEnable_IMM12_10 0 "invalid" 1 "Read SW-Version" 2 "Read HW-Version" 3 "Barcode" ;
VAL_ 2332109979 M2I_Byrack_Enable_IMM12_11 1 "Deactive" 2 "Active" ;
VAL_ 2332109979 M2I_Byrack_ReVeEnable_IMM12_11 0 "invalid" 1 "Read SW-Version" 2 "Read HW-Version" 3 "Barcode" ;
VAL_ 2332109980 M2I_Byrack_Enable_IMM12_12 1 "Deactive" 2 "Active" ;
VAL_ 2332109980 M2I_Byrack_ReVeEnable_IMM12_12 0 "invalid" 1 "Read SW-Version" 2 "Read HW-Version" 3 "Barcode" ;
VAL_ 2332109981 M2I_Byrack_Enable_IMM12_13 1 "Deactive" 2 "Active" ;
VAL_ 2332109981 M2I_Byrack_ReVeEnable_IMM12_13 0 "invalid" 1 "Read SW-Version" 2 "Read HW-Version" 3 "Barcode" ;
VAL_ 2332109982 M2I_Byrack_Enable_IMM12_14 1 "Deactive" 2 "Active" ;
VAL_ 2332109982 M2I_Byrack_ReVeEnable_IMM12_14 0 "invalid" 1 "Read SW-Version" 2 "Read HW-Version" 3 "Barcode" ;
VAL_ 2332109983 M2I_Byrack_Enable_IMM12_15 1 "Deactive" 2 "Active" ;
VAL_ 2332109983 M2I_Byrack_ReVeEnable_IMM12_15 0 "invalid" 1 "Read SW-Version" 2 "Read HW-Version" 3 "Barcode" ;
VAL_ 2332109984 M2I_Byrack_Enable_IMM12_16 1 "Deactive" 2 "Active" ;
VAL_ 2332109984 M2I_Byrack_ReVeEnable_IMM12_16 0 "invalid" 1 "Read SW-Version" 2 "Read HW-Version" 3 "Barcode" ;
VAL_ 2332109985 M2I_Byrack_Enable_IMM12_17 1 "Deactive" 2 "Active" ;
VAL_ 2332109985 M2I_Byrack_ReVeEnable_IMM12_17 0 "invalid" 1 "Read SW-Version" 2 "Read HW-Version" 3 "Barcode" ;
VAL_ 2332109986 M2I_Byrack_Enable_IMM12_18 1 "Deactive" 2 "Active" ;
VAL_ 2332109986 M2I_Byrack_ReVeEnable_IMM12_18 0 "invalid" 1 "Read SW-Version" 2 "Read HW-Version" 3 "Barcode" ;
VAL_ 2332109987 M2I_Byrack_Enable_IMM12_19 1 "Deactive" 2 "Active" ;
VAL_ 2332109987 M2I_Byrack_ReVeEnable_IMM12_19 0 "invalid" 1 "Read SW-Version" 2 "Read HW-Version" 3 "Barcode" ;
VAL_ 2332109988 M2I_Byrack_Enable_IMM12_20 1 "Deactive" 2 "Active" ;
VAL_ 2332109988 M2I_Byrack_ReVeEnable_IMM12_20 0 "invalid" 1 "Read SW-Version" 2 "Read HW-Version" 3 "Barcode" ;
VAL_ 2332109989 M2I_Byrack_Enable_IMM12_21 1 "Deactive" 2 "Active" ;
VAL_ 2332109989 M2I_Byrack_ReVeEnable_IMM12_21 0 "invalid" 1 "Read SW-Version" 2 "Read HW-Version" 3 "Barcode" ;
VAL_ 2332109990 M2I_Byrack_Enable_IMM12_22 1 "Deactive" 2 "Active" ;
VAL_ 2332109990 M2I_Byrack_ReVeEnable_IMM12_22 0 "invalid" 1 "Read SW-Version" 2 "Read HW-Version" 3 "Barcode" ;
VAL_ 2332109991 M2I_Byrack_Enable_IMM12_23 1 "Deactive" 2 "Active" ;
VAL_ 2332109991 M2I_Byrack_ReVeEnable_IMM12_23 0 "invalid" 1 "Read SW-Version" 2 "Read HW-Version" 3 "Barcode" ;
VAL_ 2332109992 M2I_Byrack_Enable_IMM12_24 1 "Deactive" 2 "Active" ;
VAL_ 2332109992 M2I_Byrack_ReVeEnable_IMM12_24 0 "invalid" 1 "Read SW-Version" 2 "Read HW-Version" 3 "Barcode" ;
VAL_ 2332109993 M2I_Byrack_Enable_IMM12_25 1 "Deactive" 2 "Active" ;
VAL_ 2332109993 M2I_Byrack_ReVeEnable_IMM12_25 0 "invalid" 1 "Read SW-Version" 2 "Read HW-Version" 3 "Barcode" ;
VAL_ 2332109994 M2I_Byrack_Enable_IMM12_26 1 "Deactive" 2 "Active" ;
VAL_ 2332109994 M2I_Byrack_ReVeEnable_IMM12_26 0 "invalid" 1 "Read SW-Version" 2 "Read HW-Version" 3 "Barcode" ;
VAL_ 2332109995 M2I_Byrack_Enable_IMM12_27 1 "Deactive" 2 "Active" ;
VAL_ 2332109995 M2I_Byrack_ReVeEnable_IMM12_27 0 "invalid" 1 "Read SW-Version" 2 "Read HW-Version" 3 "Barcode" ;
VAL_ 2332109996 M2I_Byrack_Enable_IMM12_28 1 "Deactive" 2 "Active" ;
VAL_ 2332109996 M2I_Byrack_ReVeEnable_IMM12_28 0 "invalid" 1 "Read SW-Version" 2 "Read HW-Version" 3 "Barcode" ;
VAL_ 2332109997 M2I_Byrack_Enable_IMM12_29 1 "Deactive" 2 "Active" ;
VAL_ 2332109997 M2I_Byrack_ReVeEnable_IMM12_29 0 "invalid" 1 "Read SW-Version" 2 "Read HW-Version" 3 "Barcode" ;
VAL_ 2332109998 M2I_Byrack_Enable_IMM12_30 1 "Deactive" 2 "Active" ;
VAL_ 2332109998 M2I_Byrack_ReVeEnable_IMM12_30 0 "invalid" 1 "Read SW-Version" 2 "Read HW-Version" 3 "Barcode" ;
VAL_ 2332109999 M2I_Byrack_Enable_IMM12_31 1 "Deactive" 2 "Active" ;
VAL_ 2332109999 M2I_Byrack_ReVeEnable_IMM12_31 0 "invalid" 1 "Read SW-Version" 2 "Read HW-Version" 3 "Barcode" ;
VAL_ 2332110225 M2I_Byrack_Enable_IMM13_01 1 "Deactive" 2 "Active" ;
VAL_ 2332110225 M2I_Byrack_ReVeEnable_IMM13_01 0 "invalid" 1 "Read SW-Version" 2 "Read HW-Version" 3 "Barcode" ;
VAL_ 2332110226 M2I_Byrack_Enable_IMM13_02 1 "Deactive" 2 "Active" ;
VAL_ 2332110226 M2I_Byrack_ReVeEnable_IMM13_02 0 "invalid" 1 "Read SW-Version" 2 "Read HW-Version" 3 "Barcode" ;
VAL_ 2332110227 M2I_Byrack_Enable_IMM13_03 1 "Deactive" 2 "Active" ;
VAL_ 2332110227 M2I_Byrack_ReVeEnable_IMM13_03 0 "invalid" 1 "Read SW-Version" 2 "Read HW-Version" 3 "Barcode" ;
VAL_ 2332110228 M2I_Byrack_Enable_IMM13_04 1 "Deactive" 2 "Active" ;
VAL_ 2332110228 M2I_Byrack_ReVeEnable_IMM13_04 0 "invalid" 1 "Read SW-Version" 2 "Read HW-Version" 3 "Barcode" ;
VAL_ 2332110229 M2I_Byrack_Enable_IMM13_05 1 "Deactive" 2 "Active" ;
VAL_ 2332110229 M2I_Byrack_ReVeEnable_IMM13_05 0 "invalid" 1 "Read SW-Version" 2 "Read HW-Version" 3 "Barcode" ;
VAL_ 2332110230 M2I_Byrack_Enable_IMM13_06 1 "Deactive" 2 "Active" ;
VAL_ 2332110230 M2I_Byrack_ReVeEnable_IMM13_06 0 "invalid" 1 "Read SW-Version" 2 "Read HW-Version" 3 "Barcode" ;
VAL_ 2332110231 M2I_Byrack_Enable_IMM13_07 1 "Deactive" 2 "Active" ;
VAL_ 2332110231 M2I_Byrack_ReVeEnable_IMM13_07 0 "invalid" 1 "Read SW-Version" 2 "Read HW-Version" 3 "Barcode" ;
VAL_ 2332110232 M2I_Byrack_Enable_IMM13_08 1 "Deactive" 2 "Active" ;
VAL_ 2332110232 M2I_Byrack_ReVeEnable_IMM13_08 0 "invalid" 1 "Read SW-Version" 2 "Read HW-Version" 3 "Barcode" ;
VAL_ 2332110233 M2I_Byrack_Enable_IMM13_09 1 "Deactive" 2 "Active" ;
VAL_ 2332110233 M2I_Byrack_ReVeEnable_IMM13_09 0 "invalid" 1 "Read SW-Version" 2 "Read HW-Version" 3 "Barcode" ;
VAL_ 2332110234 M2I_Byrack_Enable_IMM13_10 1 "Deactive" 2 "Active" ;
VAL_ 2332110234 M2I_Byrack_ReVeEnable_IMM13_10 0 "invalid" 1 "Read SW-Version" 2 "Read HW-Version" 3 "Barcode" ;
VAL_ 2332110235 M2I_Byrack_Enable_IMM13_11 1 "Deactive" 2 "Active" ;
VAL_ 2332110235 M2I_Byrack_ReVeEnable_IMM13_11 0 "invalid" 1 "Read SW-Version" 2 "Read HW-Version" 3 "Barcode" ;
VAL_ 2332110236 M2I_Byrack_Enable_IMM13_12 1 "Deactive" 2 "Active" ;
VAL_ 2332110236 M2I_Byrack_ReVeEnable_IMM13_12 0 "invalid" 1 "Read SW-Version" 2 "Read HW-Version" 3 "Barcode" ;
VAL_ 2332110237 M2I_Byrack_Enable_IMM13_13 1 "Deactive" 2 "Active" ;
VAL_ 2332110237 M2I_Byrack_ReVeEnable_IMM13_13 0 "invalid" 1 "Read SW-Version" 2 "Read HW-Version" 3 "Barcode" ;
VAL_ 2332110238 M2I_Byrack_Enable_IMM13_14 1 "Deactive" 2 "Active" ;
VAL_ 2332110238 M2I_Byrack_ReVeEnable_IMM13_14 0 "invalid" 1 "Read SW-Version" 2 "Read HW-Version" 3 "Barcode" ;
VAL_ 2332110239 M2I_Byrack_Enable_IMM13_15 1 "Deactive" 2 "Active" ;
VAL_ 2332110239 M2I_Byrack_ReVeEnable_IMM13_15 0 "invalid" 1 "Read SW-Version" 2 "Read HW-Version" 3 "Barcode" ;
VAL_ 2332110240 M2I_Byrack_Enable_IMM13_16 1 "Deactive" 2 "Active" ;
VAL_ 2332110240 M2I_Byrack_ReVeEnable_IMM13_16 0 "invalid" 1 "Read SW-Version" 2 "Read HW-Version" 3 "Barcode" ;
VAL_ 2332110241 M2I_Byrack_Enable_IMM13_17 1 "Deactive" 2 "Active" ;
VAL_ 2332110241 M2I_Byrack_ReVeEnable_IMM13_17 0 "invalid" 1 "Read SW-Version" 2 "Read HW-Version" 3 "Barcode" ;
VAL_ 2332110242 M2I_Byrack_Enable_IMM13_18 1 "Deactive" 2 "Active" ;
VAL_ 2332110242 M2I_Byrack_ReVeEnable_IMM13_18 0 "invalid" 1 "Read SW-Version" 2 "Read HW-Version" 3 "Barcode" ;
VAL_ 2332110243 M2I_Byrack_Enable_IMM13_19 1 "Deactive" 2 "Active" ;
VAL_ 2332110243 M2I_Byrack_ReVeEnable_IMM13_19 0 "invalid" 1 "Read SW-Version" 2 "Read HW-Version" 3 "Barcode" ;
VAL_ 2332110244 M2I_Byrack_Enable_IMM13_20 1 "Deactive" 2 "Active" ;
VAL_ 2332110244 M2I_Byrack_ReVeEnable_IMM13_20 0 "invalid" 1 "Read SW-Version" 2 "Read HW-Version" 3 "Barcode" ;
VAL_ 2332110245 M2I_Byrack_Enable_IMM13_21 1 "Deactive" 2 "Active" ;
VAL_ 2332110245 M2I_Byrack_ReVeEnable_IMM13_21 0 "invalid" 1 "Read SW-Version" 2 "Read HW-Version" 3 "Barcode" ;
VAL_ 2332110246 M2I_Byrack_Enable_IMM13_22 1 "Deactive" 2 "Active" ;
VAL_ 2332110246 M2I_Byrack_ReVeEnable_IMM13_22 0 "invalid" 1 "Read SW-Version" 2 "Read HW-Version" 3 "Barcode" ;
VAL_ 2332110247 M2I_Byrack_Enable_IMM13_23 1 "Deactive" 2 "Active" ;
VAL_ 2332110247 M2I_Byrack_ReVeEnable_IMM13_23 0 "invalid" 1 "Read SW-Version" 2 "Read HW-Version" 3 "Barcode" ;
VAL_ 2332110248 M2I_Byrack_Enable_IMM13_24 1 "Deactive" 2 "Active" ;
VAL_ 2332110248 M2I_Byrack_ReVeEnable_IMM13_24 0 "invalid" 1 "Read SW-Version" 2 "Read HW-Version" 3 "Barcode" ;
VAL_ 2332110249 M2I_Byrack_Enable_IMM13_25 1 "Deactive" 2 "Active" ;
VAL_ 2332110249 M2I_Byrack_ReVeEnable_IMM13_25 0 "invalid" 1 "Read SW-Version" 2 "Read HW-Version" 3 "Barcode" ;
VAL_ 2332110250 M2I_Byrack_Enable_IMM13_26 1 "Deactive" 2 "Active" ;
VAL_ 2332110250 M2I_Byrack_ReVeEnable_IMM13_26 0 "invalid" 1 "Read SW-Version" 2 "Read HW-Version" 3 "Barcode" ;
VAL_ 2332110251 M2I_Byrack_Enable_IMM13_27 1 "Deactive" 2 "Active" ;
VAL_ 2332110251 M2I_Byrack_ReVeEnable_IMM13_27 0 "invalid" 1 "Read SW-Version" 2 "Read HW-Version" 3 "Barcode" ;
VAL_ 2332110252 M2I_Byrack_Enable_IMM13_28 1 "Deactive" 2 "Active" ;
VAL_ 2332110252 M2I_Byrack_ReVeEnable_IMM13_28 0 "invalid" 1 "Read SW-Version" 2 "Read HW-Version" 3 "Barcode" ;
VAL_ 2332110253 M2I_Byrack_Enable_IMM13_29 1 "Deactive" 2 "Active" ;
VAL_ 2332110253 M2I_Byrack_ReVeEnable_IMM13_29 0 "invalid" 1 "Read SW-Version" 2 "Read HW-Version" 3 "Barcode" ;
VAL_ 2332110254 M2I_Byrack_Enable_IMM13_30 1 "Deactive" 2 "Active" ;
VAL_ 2332110254 M2I_Byrack_ReVeEnable_IMM13_30 0 "invalid" 1 "Read SW-Version" 2 "Read HW-Version" 3 "Barcode" ;
VAL_ 2332110255 M2I_Byrack_Enable_IMM13_31 1 "Deactive" 2 "Active" ;
VAL_ 2332110255 M2I_Byrack_ReVeEnable_IMM13_31 0 "invalid" 1 "Read SW-Version" 2 "Read HW-Version" 3 "Barcode" ;
VAL_ 2332110481 M2I_Byrack_Enable_IMM14_01 1 "Deactive" 2 "Active" ;
VAL_ 2332110481 M2I_Byrack_ReVeEnable_IMM14_01 0 "invalid" 1 "Read SW-Version" 2 "Read HW-Version" 3 "Barcode" ;
VAL_ 2332110482 M2I_Byrack_Enable_IMM14_02 1 "Deactive" 2 "Active" ;
VAL_ 2332110482 M2I_Byrack_ReVeEnable_IMM14_02 0 "invalid" 1 "Read SW-Version" 2 "Read HW-Version" 3 "Barcode" ;
VAL_ 2332110483 M2I_Byrack_Enable_IMM14_03 1 "Deactive" 2 "Active" ;
VAL_ 2332110483 M2I_Byrack_ReVeEnable_IMM14_03 0 "invalid" 1 "Read SW-Version" 2 "Read HW-Version" 3 "Barcode" ;
VAL_ 2332110484 M2I_Byrack_Enable_IMM14_04 1 "Deactive" 2 "Active" ;
VAL_ 2332110484 M2I_Byrack_ReVeEnable_IMM14_04 0 "invalid" 1 "Read SW-Version" 2 "Read HW-Version" 3 "Barcode" ;
VAL_ 2332110485 M2I_Byrack_Enable_IMM14_05 1 "Deactive" 2 "Active" ;
VAL_ 2332110485 M2I_Byrack_ReVeEnable_IMM14_05 0 "invalid" 1 "Read SW-Version" 2 "Read HW-Version" 3 "Barcode" ;
VAL_ 2332110486 M2I_Byrack_Enable_IMM14_06 1 "Deactive" 2 "Active" ;
VAL_ 2332110486 M2I_Byrack_ReVeEnable_IMM14_06 0 "invalid" 1 "Read SW-Version" 2 "Read HW-Version" 3 "Barcode" ;
VAL_ 2332110487 M2I_Byrack_Enable_IMM14_07 1 "Deactive" 2 "Active" ;
VAL_ 2332110487 M2I_Byrack_ReVeEnable_IMM14_07 0 "invalid" 1 "Read SW-Version" 2 "Read HW-Version" 3 "Barcode" ;
VAL_ 2332110488 M2I_Byrack_Enable_IMM14_08 1 "Deactive" 2 "Active" ;
VAL_ 2332110488 M2I_Byrack_ReVeEnable_IMM14_08 0 "invalid" 1 "Read SW-Version" 2 "Read HW-Version" 3 "Barcode" ;
VAL_ 2332110489 M2I_Byrack_Enable_IMM14_09 1 "Deactive" 2 "Active" ;
VAL_ 2332110489 M2I_Byrack_ReVeEnable_IMM14_09 0 "invalid" 1 "Read SW-Version" 2 "Read HW-Version" 3 "Barcode" ;
VAL_ 2332110490 M2I_Byrack_Enable_IMM14_10 1 "Deactive" 2 "Active" ;
VAL_ 2332110490 M2I_Byrack_ReVeEnable_IMM14_10 0 "invalid" 1 "Read SW-Version" 2 "Read HW-Version" 3 "Barcode" ;
VAL_ 2332110491 M2I_Byrack_Enable_IMM14_11 1 "Deactive" 2 "Active" ;
VAL_ 2332110491 M2I_Byrack_ReVeEnable_IMM14_11 0 "invalid" 1 "Read SW-Version" 2 "Read HW-Version" 3 "Barcode" ;
VAL_ 2332110492 M2I_Byrack_Enable_IMM14_12 1 "Deactive" 2 "Active" ;
VAL_ 2332110492 M2I_Byrack_ReVeEnable_IMM14_12 0 "invalid" 1 "Read SW-Version" 2 "Read HW-Version" 3 "Barcode" ;
VAL_ 2332110493 M2I_Byrack_Enable_IMM14_13 1 "Deactive" 2 "Active" ;
VAL_ 2332110493 M2I_Byrack_ReVeEnable_IMM14_13 0 "invalid" 1 "Read SW-Version" 2 "Read HW-Version" 3 "Barcode" ;
VAL_ 2332110494 M2I_Byrack_Enable_IMM14_14 1 "Deactive" 2 "Active" ;
VAL_ 2332110494 M2I_Byrack_ReVeEnable_IMM14_14 0 "invalid" 1 "Read SW-Version" 2 "Read HW-Version" 3 "Barcode" ;
VAL_ 2332110495 M2I_Byrack_Enable_IMM14_15 1 "Deactive" 2 "Active" ;
VAL_ 2332110495 M2I_Byrack_ReVeEnable_IMM14_15 0 "invalid" 1 "Read SW-Version" 2 "Read HW-Version" 3 "Barcode" ;
VAL_ 2332110496 M2I_Byrack_Enable_IMM14_16 1 "Deactive" 2 "Active" ;
VAL_ 2332110496 M2I_Byrack_ReVeEnable_IMM14_16 0 "invalid" 1 "Read SW-Version" 2 "Read HW-Version" 3 "Barcode" ;
VAL_ 2332110497 M2I_Byrack_Enable_IMM14_17 1 "Deactive" 2 "Active" ;
VAL_ 2332110497 M2I_Byrack_ReVeEnable_IMM14_17 0 "invalid" 1 "Read SW-Version" 2 "Read HW-Version" 3 "Barcode" ;
VAL_ 2332110498 M2I_Byrack_Enable_IMM14_18 1 "Deactive" 2 "Active" ;
VAL_ 2332110498 M2I_Byrack_ReVeEnable_IMM14_18 0 "invalid" 1 "Read SW-Version" 2 "Read HW-Version" 3 "Barcode" ;
VAL_ 2332110499 M2I_Byrack_Enable_IMM14_19 1 "Deactive" 2 "Active" ;
VAL_ 2332110499 M2I_Byrack_ReVeEnable_IMM14_19 0 "invalid" 1 "Read SW-Version" 2 "Read HW-Version" 3 "Barcode" ;
VAL_ 2332110500 M2I_Byrack_Enable_IMM14_20 1 "Deactive" 2 "Active" ;
VAL_ 2332110500 M2I_Byrack_ReVeEnable_IMM14_20 0 "invalid" 1 "Read SW-Version" 2 "Read HW-Version" 3 "Barcode" ;
VAL_ 2332110501 M2I_Byrack_Enable_IMM14_21 1 "Deactive" 2 "Active" ;
VAL_ 2332110501 M2I_Byrack_ReVeEnable_IMM14_21 0 "invalid" 1 "Read SW-Version" 2 "Read HW-Version" 3 "Barcode" ;
VAL_ 2332110502 M2I_Byrack_Enable_IMM14_22 1 "Deactive" 2 "Active" ;
VAL_ 2332110502 M2I_Byrack_ReVeEnable_IMM14_22 0 "invalid" 1 "Read SW-Version" 2 "Read HW-Version" 3 "Barcode" ;
VAL_ 2332110503 M2I_Byrack_Enable_IMM14_23 1 "Deactive" 2 "Active" ;
VAL_ 2332110503 M2I_Byrack_ReVeEnable_IMM14_23 0 "invalid" 1 "Read SW-Version" 2 "Read HW-Version" 3 "Barcode" ;
VAL_ 2332110504 M2I_Byrack_Enable_IMM14_24 1 "Deactive" 2 "Active" ;
VAL_ 2332110504 M2I_Byrack_ReVeEnable_IMM14_24 0 "invalid" 1 "Read SW-Version" 2 "Read HW-Version" 3 "Barcode" ;
VAL_ 2332110505 M2I_Byrack_Enable_IMM14_25 1 "Deactive" 2 "Active" ;
VAL_ 2332110505 M2I_Byrack_ReVeEnable_IMM14_25 0 "invalid" 1 "Read SW-Version" 2 "Read HW-Version" 3 "Barcode" ;
VAL_ 2332110506 M2I_Byrack_Enable_IMM14_26 1 "Deactive" 2 "Active" ;
VAL_ 2332110506 M2I_Byrack_ReVeEnable_IMM14_26 0 "invalid" 1 "Read SW-Version" 2 "Read HW-Version" 3 "Barcode" ;
VAL_ 2332110507 M2I_Byrack_Enable_IMM14_27 1 "Deactive" 2 "Active" ;
VAL_ 2332110507 M2I_Byrack_ReVeEnable_IMM14_27 0 "invalid" 1 "Read SW-Version" 2 "Read HW-Version" 3 "Barcode" ;
VAL_ 2332110508 M2I_Byrack_Enable_IMM14_28 1 "Deactive" 2 "Active" ;
VAL_ 2332110508 M2I_Byrack_ReVeEnable_IMM14_28 0 "invalid" 1 "Read SW-Version" 2 "Read HW-Version" 3 "Barcode" ;
VAL_ 2332110509 M2I_Byrack_Enable_IMM14_29 1 "Deactive" 2 "Active" ;
VAL_ 2332110509 M2I_Byrack_ReVeEnable_IMM14_29 0 "invalid" 1 "Read SW-Version" 2 "Read HW-Version" 3 "Barcode" ;
VAL_ 2332110510 M2I_Byrack_Enable_IMM14_30 1 "Deactive" 2 "Active" ;
VAL_ 2332110510 M2I_Byrack_ReVeEnable_IMM14_30 0 "invalid" 1 "Read SW-Version" 2 "Read HW-Version" 3 "Barcode" ;
VAL_ 2332110511 M2I_Byrack_Enable_IMM14_31 1 "Deactive" 2 "Active" ;
VAL_ 2332110511 M2I_Byrack_ReVeEnable_IMM14_31 0 "invalid" 1 "Read SW-Version" 2 "Read HW-Version" 3 "Barcode" ;
VAL_ 2332110737 M2I_Byrack_Enable_IMM15_01 1 "Deactive" 2 "Active" ;
VAL_ 2332110737 M2I_Byrack_ReVeEnable_IMM15_01 0 "invalid" 1 "Read SW-Version" 2 "Read HW-Version" 3 "Barcode" ;
VAL_ 2332110738 M2I_Byrack_Enable_IMM15_02 1 "Deactive" 2 "Active" ;
VAL_ 2332110738 M2I_Byrack_ReVeEnable_IMM15_02 0 "invalid" 1 "Read SW-Version" 2 "Read HW-Version" 3 "Barcode" ;
VAL_ 2332110739 M2I_Byrack_Enable_IMM15_03 1 "Deactive" 2 "Active" ;
VAL_ 2332110739 M2I_Byrack_ReVeEnable_IMM15_03 0 "invalid" 1 "Read SW-Version" 2 "Read HW-Version" 3 "Barcode" ;
VAL_ 2332110740 M2I_Byrack_Enable_IMM15_04 1 "Deactive" 2 "Active" ;
VAL_ 2332110740 M2I_Byrack_ReVeEnable_IMM15_04 0 "invalid" 1 "Read SW-Version" 2 "Read HW-Version" 3 "Barcode" ;
VAL_ 2332110741 M2I_Byrack_Enable_IMM15_05 1 "Deactive" 2 "Active" ;
VAL_ 2332110741 M2I_Byrack_ReVeEnable_IMM15_05 0 "invalid" 1 "Read SW-Version" 2 "Read HW-Version" 3 "Barcode" ;
VAL_ 2332110742 M2I_Byrack_Enable_IMM15_06 1 "Deactive" 2 "Active" ;
VAL_ 2332110742 M2I_Byrack_ReVeEnable_IMM15_06 0 "invalid" 1 "Read SW-Version" 2 "Read HW-Version" 3 "Barcode" ;
VAL_ 2332110743 M2I_Byrack_Enable_IMM15_07 1 "Deactive" 2 "Active" ;
VAL_ 2332110743 M2I_Byrack_ReVeEnable_IMM15_07 0 "invalid" 1 "Read SW-Version" 2 "Read HW-Version" 3 "Barcode" ;
VAL_ 2332110744 M2I_Byrack_Enable_IMM15_08 1 "Deactive" 2 "Active" ;
VAL_ 2332110744 M2I_Byrack_ReVeEnable_IMM15_08 0 "invalid" 1 "Read SW-Version" 2 "Read HW-Version" 3 "Barcode" ;
VAL_ 2332110745 M2I_Byrack_Enable_IMM15_09 1 "Deactive" 2 "Active" ;
VAL_ 2332110745 M2I_Byrack_ReVeEnable_IMM15_09 0 "invalid" 1 "Read SW-Version" 2 "Read HW-Version" 3 "Barcode" ;
VAL_ 2332110746 M2I_Byrack_Enable_IMM15_10 1 "Deactive" 2 "Active" ;
VAL_ 2332110746 M2I_Byrack_ReVeEnable_IMM15_10 0 "invalid" 1 "Read SW-Version" 2 "Read HW-Version" 3 "Barcode" ;
VAL_ 2332110747 M2I_Byrack_Enable_IMM15_11 1 "Deactive" 2 "Active" ;
VAL_ 2332110747 M2I_Byrack_ReVeEnable_IMM15_11 0 "invalid" 1 "Read SW-Version" 2 "Read HW-Version" 3 "Barcode" ;
VAL_ 2332110748 M2I_Byrack_Enable_IMM15_12 1 "Deactive" 2 "Active" ;
VAL_ 2332110748 M2I_Byrack_ReVeEnable_IMM15_12 0 "invalid" 1 "Read SW-Version" 2 "Read HW-Version" 3 "Barcode" ;
VAL_ 2332110749 M2I_Byrack_Enable_IMM15_13 1 "Deactive" 2 "Active" ;
VAL_ 2332110749 M2I_Byrack_ReVeEnable_IMM15_13 0 "invalid" 1 "Read SW-Version" 2 "Read HW-Version" 3 "Barcode" ;
VAL_ 2332110750 M2I_Byrack_Enable_IMM15_14 1 "Deactive" 2 "Active" ;
VAL_ 2332110750 M2I_Byrack_ReVeEnable_IMM15_14 0 "invalid" 1 "Read SW-Version" 2 "Read HW-Version" 3 "Barcode" ;
VAL_ 2332110751 M2I_Byrack_Enable_IMM15_15 1 "Deactive" 2 "Active" ;
VAL_ 2332110751 M2I_Byrack_ReVeEnable_IMM15_15 0 "invalid" 1 "Read SW-Version" 2 "Read HW-Version" 3 "Barcode" ;
VAL_ 2332110752 M2I_Byrack_Enable_IMM15_16 1 "Deactive" 2 "Active" ;
VAL_ 2332110752 M2I_Byrack_ReVeEnable_IMM15_16 0 "invalid" 1 "Read SW-Version" 2 "Read HW-Version" 3 "Barcode" ;
VAL_ 2332110753 M2I_Byrack_Enable_IMM15_17 1 "Deactive" 2 "Active" ;
VAL_ 2332110753 M2I_Byrack_ReVeEnable_IMM15_17 0 "invalid" 1 "Read SW-Version" 2 "Read HW-Version" 3 "Barcode" ;
VAL_ 2332110754 M2I_Byrack_Enable_IMM15_18 1 "Deactive" 2 "Active" ;
VAL_ 2332110754 M2I_Byrack_ReVeEnable_IMM15_18 0 "invalid" 1 "Read SW-Version" 2 "Read HW-Version" 3 "Barcode" ;
VAL_ 2332110755 M2I_Byrack_Enable_IMM15_19 1 "Deactive" 2 "Active" ;
VAL_ 2332110755 M2I_Byrack_ReVeEnable_IMM15_19 0 "invalid" 1 "Read SW-Version" 2 "Read HW-Version" 3 "Barcode" ;
VAL_ 2332110756 M2I_Byrack_Enable_IMM15_20 1 "Deactive" 2 "Active" ;
VAL_ 2332110756 M2I_Byrack_ReVeEnable_IMM15_20 0 "invalid" 1 "Read SW-Version" 2 "Read HW-Version" 3 "Barcode" ;
VAL_ 2332110757 M2I_Byrack_Enable_IMM15_21 1 "Deactive" 2 "Active" ;
VAL_ 2332110757 M2I_Byrack_ReVeEnable_IMM15_21 0 "invalid" 1 "Read SW-Version" 2 "Read HW-Version" 3 "Barcode" ;
VAL_ 2332110758 M2I_Byrack_Enable_IMM15_22 1 "Deactive" 2 "Active" ;
VAL_ 2332110758 M2I_Byrack_ReVeEnable_IMM15_22 0 "invalid" 1 "Read SW-Version" 2 "Read HW-Version" 3 "Barcode" ;
VAL_ 2332110759 M2I_Byrack_Enable_IMM15_23 1 "Deactive" 2 "Active" ;
VAL_ 2332110759 M2I_Byrack_ReVeEnable_IMM15_23 0 "invalid" 1 "Read SW-Version" 2 "Read HW-Version" 3 "Barcode" ;
VAL_ 2332110760 M2I_Byrack_Enable_IMM15_24 1 "Deactive" 2 "Active" ;
VAL_ 2332110760 M2I_Byrack_ReVeEnable_IMM15_24 0 "invalid" 1 "Read SW-Version" 2 "Read HW-Version" 3 "Barcode" ;
VAL_ 2332110761 M2I_Byrack_Enable_IMM15_25 1 "Deactive" 2 "Active" ;
VAL_ 2332110761 M2I_Byrack_ReVeEnable_IMM15_25 0 "invalid" 1 "Read SW-Version" 2 "Read HW-Version" 3 "Barcode" ;
VAL_ 2332110762 M2I_Byrack_Enable_IMM15_26 1 "Deactive" 2 "Active" ;
VAL_ 2332110762 M2I_Byrack_ReVeEnable_IMM15_26 0 "invalid" 1 "Read SW-Version" 2 "Read HW-Version" 3 "Barcode" ;
VAL_ 2332110763 M2I_Byrack_Enable_IMM15_27 1 "Deactive" 2 "Active" ;
VAL_ 2332110763 M2I_Byrack_ReVeEnable_IMM15_27 0 "invalid" 1 "Read SW-Version" 2 "Read HW-Version" 3 "Barcode" ;
VAL_ 2332110764 M2I_Byrack_Enable_IMM15_28 1 "Deactive" 2 "Active" ;
VAL_ 2332110764 M2I_Byrack_ReVeEnable_IMM15_28 0 "invalid" 1 "Read SW-Version" 2 "Read HW-Version" 3 "Barcode" ;
VAL_ 2332110765 M2I_Byrack_Enable_IMM15_29 1 "Deactive" 2 "Active" ;
VAL_ 2332110765 M2I_Byrack_ReVeEnable_IMM15_29 0 "invalid" 1 "Read SW-Version" 2 "Read HW-Version" 3 "Barcode" ;
VAL_ 2332110766 M2I_Byrack_Enable_IMM15_30 1 "Deactive" 2 "Active" ;
VAL_ 2332110766 M2I_Byrack_ReVeEnable_IMM15_30 0 "invalid" 1 "Read SW-Version" 2 "Read HW-Version" 3 "Barcode" ;
VAL_ 2332110767 M2I_Byrack_Enable_IMM15_31 1 "Deactive" 2 "Active" ;
VAL_ 2332110767 M2I_Byrack_ReVeEnable_IMM15_31 0 "invalid" 1 "Read SW-Version" 2 "Read HW-Version" 3 "Barcode" ;
VAL_ 2332110993 M2I_Byrack_Enable_IMM16_01 1 "Deactive" 2 "Active" ;
VAL_ 2332110993 M2I_Byrack_ReVeEnable_IMM16_01 0 "invalid" 1 "Read SW-Version" 2 "Read HW-Version" 3 "Barcode" ;
VAL_ 2332110994 M2I_Byrack_Enable_IMM16_02 1 "Deactive" 2 "Active" ;
VAL_ 2332110994 M2I_Byrack_ReVeEnable_IMM16_02 0 "invalid" 1 "Read SW-Version" 2 "Read HW-Version" 3 "Barcode" ;
VAL_ 2332110995 M2I_Byrack_Enable_IMM16_03 1 "Deactive" 2 "Active" ;
VAL_ 2332110995 M2I_Byrack_ReVeEnable_IMM16_03 0 "invalid" 1 "Read SW-Version" 2 "Read HW-Version" 3 "Barcode" ;
VAL_ 2332110996 M2I_Byrack_Enable_IMM16_04 1 "Deactive" 2 "Active" ;
VAL_ 2332110996 M2I_Byrack_ReVeEnable_IMM16_04 0 "invalid" 1 "Read SW-Version" 2 "Read HW-Version" 3 "Barcode" ;
VAL_ 2332110997 M2I_Byrack_Enable_IMM16_05 1 "Deactive" 2 "Active" ;
VAL_ 2332110997 M2I_Byrack_ReVeEnable_IMM16_05 0 "invalid" 1 "Read SW-Version" 2 "Read HW-Version" 3 "Barcode" ;
VAL_ 2332110998 M2I_Byrack_Enable_IMM16_06 1 "Deactive" 2 "Active" ;
VAL_ 2332110998 M2I_Byrack_ReVeEnable_IMM16_06 0 "invalid" 1 "Read SW-Version" 2 "Read HW-Version" 3 "Barcode" ;
VERSION ""

NS_ :

BS_:

BU_: MBMU PC SBMU IMM ETH DCDC LEMS

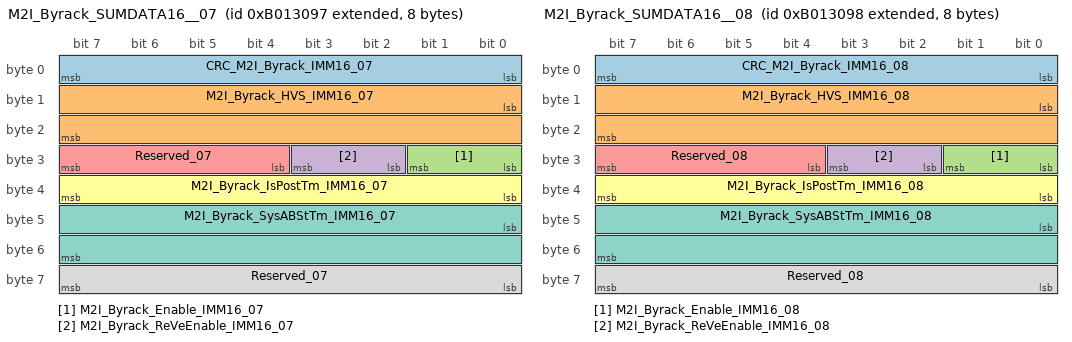
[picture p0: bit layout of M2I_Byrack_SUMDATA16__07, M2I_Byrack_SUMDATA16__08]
BO_ 2332110999 M2I_Byrack_SUMDATA16__07: 8 MBMU
 SG_ CRC_M2I_Byrack_IMM16_07 : 0|8@1+ (1,0) [0|255] ""  IMM
 SG_ M2I_Byrack_HVS_IMM16_07 : 8|16@1+ (0.1,0) [0|6553.5] "v"  IMM
 SG_ M2I_Byrack_Enable_IMM16_07 : 24|2@1+ (1,0) [0|3] ""  IMM
 SG_ M2I_Byrack_ReVeEnable_IMM16_07 : 26|2@1+ (1,0) [0|3] ""  IMM
 SG_ Reserved_07 : 28|4@1+ (1,0) [0|15] ""  IMM
 SG_ M2I_Byrack_IsPostTm_IMM16_07 : 32|8@1+ (0.01,0) [0|2.55] "s"  IMM
 SG_ M2I_Byrack_SysABStTm_IMM16_07 : 40|16@1+ (0.01,0) [0|655.35] "s"  IMM
 SG_ Reserved_07 : 56|8@1+ (1,0) [0|255] ""  IMM

BO_ 2332111000 M2I_Byrack_SUMDATA16__08: 8 MBMU
 SG_ CRC_M2I_Byrack_IMM16_08 : 0|8@1+ (1,0) [0|255] ""  IMM
 SG_ M2I_Byrack_HVS_IMM16_08 : 8|16@1+ (0.1,0) [0|6553.5] "v"  IMM
 SG_ M2I_Byrack_Enable_IMM16_08 : 24|2@1+ (1,0) [0|3] ""  IMM
 SG_ M2I_Byrack_ReVeEnable_IMM16_08 : 26|2@1+ (1,0) [0|3] ""  IMM
 SG_ Reserved_08 : 28|4@1+ (1,0) [0|15] ""  IMM
 SG_ M2I_Byrack_IsPostTm_IMM16_08 : 32|8@1+ (0.01,0) [0|2.55] "s"  IMM
 SG_ M2I_Byrack_SysABStTm_IMM16_08 : 40|16@1+ (0.01,0) [0|655.35] "s"  IMM
 SG_ Reserved_08 : 56|8@1+ (1,0) [0|255] ""  IMM

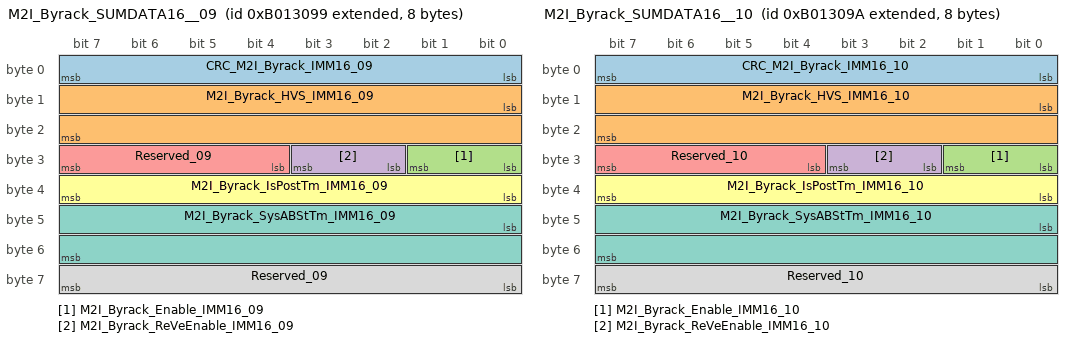
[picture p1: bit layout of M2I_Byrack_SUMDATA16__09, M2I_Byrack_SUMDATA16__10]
BO_ 2332111001 M2I_Byrack_SUMDATA16__09: 8 MBMU
 SG_ CRC_M2I_Byrack_IMM16_09 : 0|8@1+ (1,0) [0|255] ""  IMM
 SG_ M2I_Byrack_HVS_IMM16_09 : 8|16@1+ (0.1,0) [0|6553.5] "v"  IMM
 SG_ M2I_Byrack_Enable_IMM16_09 : 24|2@1+ (1,0) [0|3] ""  IMM
 SG_ M2I_Byrack_ReVeEnable_IMM16_09 : 26|2@1+ (1,0) [0|3] ""  IMM
 SG_ Reserved_09 : 28|4@1+ (1,0) [0|15] ""  IMM
 SG_ M2I_Byrack_IsPostTm_IMM16_09 : 32|8@1+ (0.01,0) [0|2.55] "s"  IMM
 SG_ M2I_Byrack_SysABStTm_IMM16_09 : 40|16@1+ (0.01,0) [0|655.35] "s"  IMM
 SG_ Reserved_09 : 56|8@1+ (1,0) [0|255] ""  IMM

BO_ 2332111002 M2I_Byrack_SUMDATA16__10: 8 MBMU
 SG_ CRC_M2I_Byrack_IMM16_10 : 0|8@1+ (1,0) [0|255] ""  IMM
 SG_ M2I_Byrack_HVS_IMM16_10 : 8|16@1+ (0.1,0) [0|6553.5] "v"  IMM
 SG_ M2I_Byrack_Enable_IMM16_10 : 24|2@1+ (1,0) [0|3] ""  IMM
 SG_ M2I_Byrack_ReVeEnable_IMM16_10 : 26|2@1+ (1,0) [0|3] ""  IMM
 SG_ Reserved_10 : 28|4@1+ (1,0) [0|15] ""  IMM
 SG_ M2I_Byrack_IsPostTm_IMM16_10 : 32|8@1+ (0.01,0) [0|2.55] "s"  IMM
 SG_ M2I_Byrack_SysABStTm_IMM16_10 : 40|16@1+ (0.01,0) [0|655.35] "s"  IMM
 SG_ Reserved_10 : 56|8@1+ (1,0) [0|255] ""  IMM

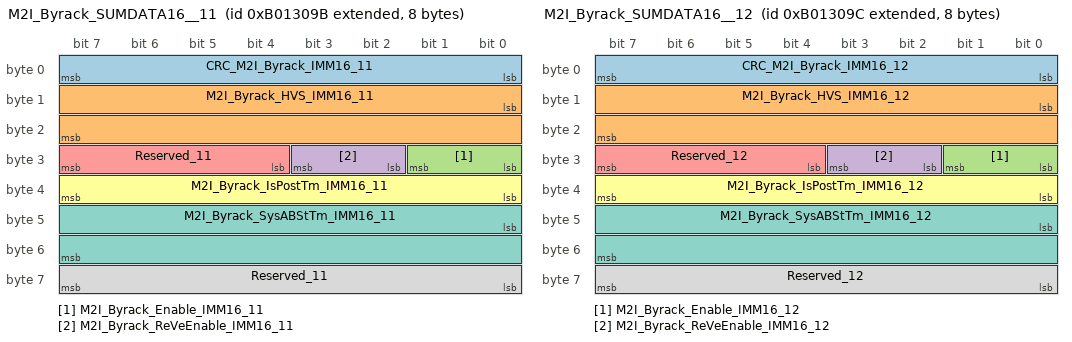
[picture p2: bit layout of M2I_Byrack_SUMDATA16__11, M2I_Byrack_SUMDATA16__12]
BO_ 2332111003 M2I_Byrack_SUMDATA16__11: 8 MBMU
 SG_ CRC_M2I_Byrack_IMM16_11 : 0|8@1+ (1,0) [0|255] ""  IMM
 SG_ M2I_Byrack_HVS_IMM16_11 : 8|16@1+ (0.1,0) [0|6553.5] "v"  IMM
 SG_ M2I_Byrack_Enable_IMM16_11 : 24|2@1+ (1,0) [0|3] ""  IMM
 SG_ M2I_Byrack_ReVeEnable_IMM16_11 : 26|2@1+ (1,0) [0|3] ""  IMM
 SG_ Reserved_11 : 28|4@1+ (1,0) [0|15] ""  IMM
 SG_ M2I_Byrack_IsPostTm_IMM16_11 : 32|8@1+ (0.01,0) [0|2.55] "s"  IMM
 SG_ M2I_Byrack_SysABStTm_IMM16_11 : 40|16@1+ (0.01,0) [0|655.35] "s"  IMM
 SG_ Reserved_11 : 56|8@1+ (1,0) [0|255] ""  IMM

BO_ 2332111004 M2I_Byrack_SUMDATA16__12: 8 MBMU
 SG_ CRC_M2I_Byrack_IMM16_12 : 0|8@1+ (1,0) [0|255] ""  IMM
 SG_ M2I_Byrack_HVS_IMM16_12 : 8|16@1+ (0.1,0) [0|6553.5] "v"  IMM
 SG_ M2I_Byrack_Enable_IMM16_12 : 24|2@1+ (1,0) [0|3] ""  IMM
 SG_ M2I_Byrack_ReVeEnable_IMM16_12 : 26|2@1+ (1,0) [0|3] ""  IMM
 SG_ Reserved_12 : 28|4@1+ (1,0) [0|15] ""  IMM
 SG_ M2I_Byrack_IsPostTm_IMM16_12 : 32|8@1+ (0.01,0) [0|2.55] "s"  IMM
 SG_ M2I_Byrack_SysABStTm_IMM16_12 : 40|16@1+ (0.01,0) [0|655.35] "s"  IMM
 SG_ Reserved_12 : 56|8@1+ (1,0) [0|255] ""  IMM

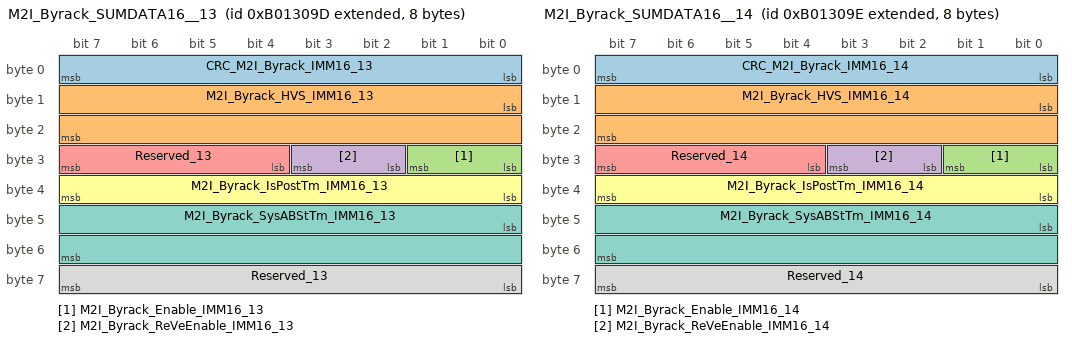
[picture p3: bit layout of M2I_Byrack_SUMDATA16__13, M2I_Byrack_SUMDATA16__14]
BO_ 2332111005 M2I_Byrack_SUMDATA16__13: 8 MBMU
 SG_ CRC_M2I_Byrack_IMM16_13 : 0|8@1+ (1,0) [0|255] ""  IMM
 SG_ M2I_Byrack_HVS_IMM16_13 : 8|16@1+ (0.1,0) [0|6553.5] "v"  IMM
 SG_ M2I_Byrack_Enable_IMM16_13 : 24|2@1+ (1,0) [0|3] ""  IMM
 SG_ M2I_Byrack_ReVeEnable_IMM16_13 : 26|2@1+ (1,0) [0|3] ""  IMM
 SG_ Reserved_13 : 28|4@1+ (1,0) [0|15] ""  IMM
 SG_ M2I_Byrack_IsPostTm_IMM16_13 : 32|8@1+ (0.01,0) [0|2.55] "s"  IMM
 SG_ M2I_Byrack_SysABStTm_IMM16_13 : 40|16@1+ (0.01,0) [0|655.35] "s"  IMM
 SG_ Reserved_13 : 56|8@1+ (1,0) [0|255] ""  IMM

BO_ 2332111006 M2I_Byrack_SUMDATA16__14: 8 MBMU
 SG_ CRC_M2I_Byrack_IMM16_14 : 0|8@1+ (1,0) [0|255] ""  IMM
 SG_ M2I_Byrack_HVS_IMM16_14 : 8|16@1+ (0.1,0) [0|6553.5] "v"  IMM
 SG_ M2I_Byrack_Enable_IMM16_14 : 24|2@1+ (1,0) [0|3] ""  IMM
 SG_ M2I_Byrack_ReVeEnable_IMM16_14 : 26|2@1+ (1,0) [0|3] ""  IMM
 SG_ Reserved_14 : 28|4@1+ (1,0) [0|15] ""  IMM
 SG_ M2I_Byrack_IsPostTm_IMM16_14 : 32|8@1+ (0.01,0) [0|2.55] "s"  IMM
 SG_ M2I_Byrack_SysABStTm_IMM16_14 : 40|16@1+ (0.01,0) [0|655.35] "s"  IMM
 SG_ Reserved_14 : 56|8@1+ (1,0) [0|255] ""  IMM

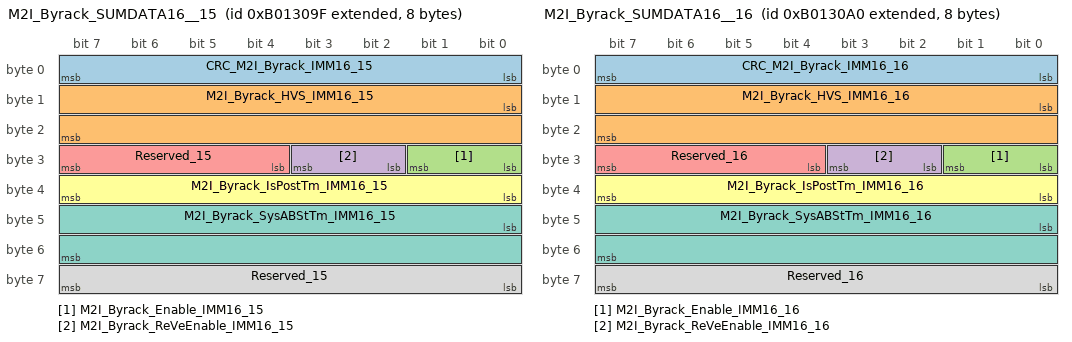
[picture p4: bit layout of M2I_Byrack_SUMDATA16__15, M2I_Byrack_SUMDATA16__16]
BO_ 2332111007 M2I_Byrack_SUMDATA16__15: 8 MBMU
 SG_ CRC_M2I_Byrack_IMM16_15 : 0|8@1+ (1,0) [0|255] ""  IMM
 SG_ M2I_Byrack_HVS_IMM16_15 : 8|16@1+ (0.1,0) [0|6553.5] "v"  IMM
 SG_ M2I_Byrack_Enable_IMM16_15 : 24|2@1+ (1,0) [0|3] ""  IMM
 SG_ M2I_Byrack_ReVeEnable_IMM16_15 : 26|2@1+ (1,0) [0|3] ""  IMM
 SG_ Reserved_15 : 28|4@1+ (1,0) [0|15] ""  IMM
 SG_ M2I_Byrack_IsPostTm_IMM16_15 : 32|8@1+ (0.01,0) [0|2.55] "s"  IMM
 SG_ M2I_Byrack_SysABStTm_IMM16_15 : 40|16@1+ (0.01,0) [0|655.35] "s"  IMM
 SG_ Reserved_15 : 56|8@1+ (1,0) [0|255] ""  IMM

BO_ 2332111008 M2I_Byrack_SUMDATA16__16: 8 MBMU
 SG_ CRC_M2I_Byrack_IMM16_16 : 0|8@1+ (1,0) [0|255] ""  IMM
 SG_ M2I_Byrack_HVS_IMM16_16 : 8|16@1+ (0.1,0) [0|6553.5] "v"  IMM
 SG_ M2I_Byrack_Enable_IMM16_16 : 24|2@1+ (1,0) [0|3] ""  IMM
 SG_ M2I_Byrack_ReVeEnable_IMM16_16 : 26|2@1+ (1,0) [0|3] ""  IMM
 SG_ Reserved_16 : 28|4@1+ (1,0) [0|15] ""  IMM
 SG_ M2I_Byrack_IsPostTm_IMM16_16 : 32|8@1+ (0.01,0) [0|2.55] "s"  IMM
 SG_ M2I_Byrack_SysABStTm_IMM16_16 : 40|16@1+ (0.01,0) [0|655.35] "s"  IMM
 SG_ Reserved_16 : 56|8@1+ (1,0) [0|255] ""  IMM

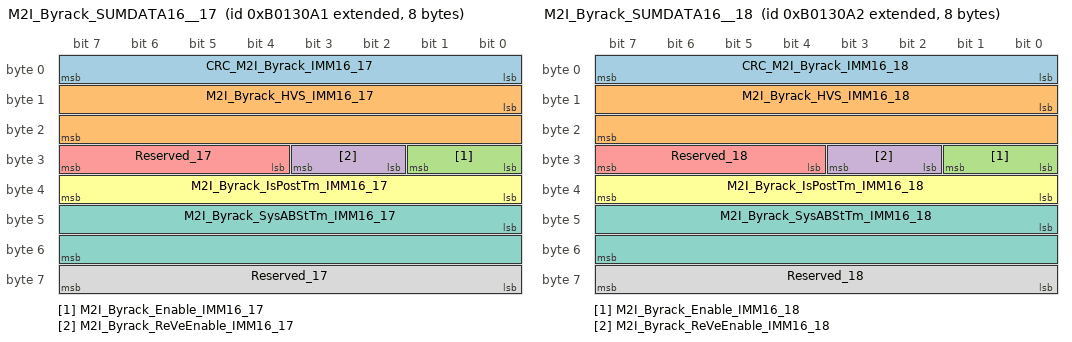
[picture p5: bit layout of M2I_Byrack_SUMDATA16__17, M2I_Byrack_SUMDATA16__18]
BO_ 2332111009 M2I_Byrack_SUMDATA16__17: 8 MBMU
 SG_ CRC_M2I_Byrack_IMM16_17 : 0|8@1+ (1,0) [0|255] ""  IMM
 SG_ M2I_Byrack_HVS_IMM16_17 : 8|16@1+ (0.1,0) [0|6553.5] "v"  IMM
 SG_ M2I_Byrack_Enable_IMM16_17 : 24|2@1+ (1,0) [0|3] ""  IMM
 SG_ M2I_Byrack_ReVeEnable_IMM16_17 : 26|2@1+ (1,0) [0|3] ""  IMM
 SG_ Reserved_17 : 28|4@1+ (1,0) [0|15] ""  IMM
 SG_ M2I_Byrack_IsPostTm_IMM16_17 : 32|8@1+ (0.01,0) [0|2.55] "s"  IMM
 SG_ M2I_Byrack_SysABStTm_IMM16_17 : 40|16@1+ (0.01,0) [0|655.35] "s"  IMM
 SG_ Reserved_17 : 56|8@1+ (1,0) [0|255] ""  IMM

BO_ 2332111010 M2I_Byrack_SUMDATA16__18: 8 MBMU
 SG_ CRC_M2I_Byrack_IMM16_18 : 0|8@1+ (1,0) [0|255] ""  IMM
 SG_ M2I_Byrack_HVS_IMM16_18 : 8|16@1+ (0.1,0) [0|6553.5] "v"  IMM
 SG_ M2I_Byrack_Enable_IMM16_18 : 24|2@1+ (1,0) [0|3] ""  IMM
 SG_ M2I_Byrack_ReVeEnable_IMM16_18 : 26|2@1+ (1,0) [0|3] ""  IMM
 SG_ Reserved_18 : 28|4@1+ (1,0) [0|15] ""  IMM
 SG_ M2I_Byrack_IsPostTm_IMM16_18 : 32|8@1+ (0.01,0) [0|2.55] "s"  IMM
 SG_ M2I_Byrack_SysABStTm_IMM16_18 : 40|16@1+ (0.01,0) [0|655.35] "s"  IMM
 SG_ Reserved_18 : 56|8@1+ (1,0) [0|255] ""  IMM

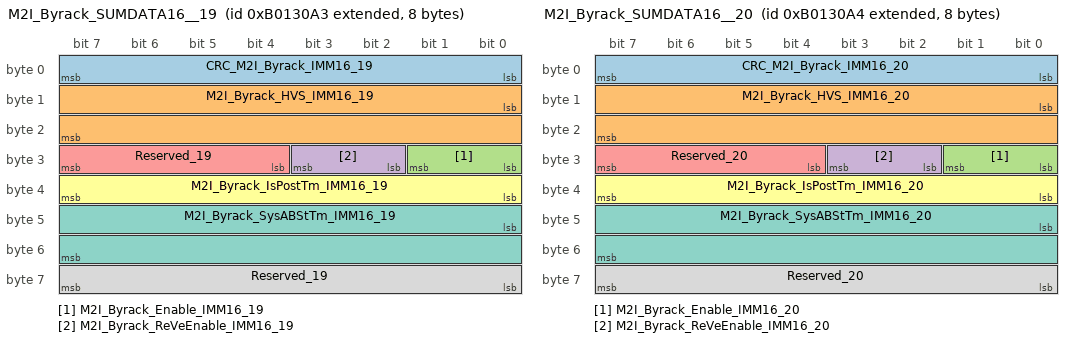
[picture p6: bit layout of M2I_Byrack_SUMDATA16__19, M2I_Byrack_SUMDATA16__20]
BO_ 2332111011 M2I_Byrack_SUMDATA16__19: 8 MBMU
 SG_ CRC_M2I_Byrack_IMM16_19 : 0|8@1+ (1,0) [0|255] ""  IMM
 SG_ M2I_Byrack_HVS_IMM16_19 : 8|16@1+ (0.1,0) [0|6553.5] "v"  IMM
 SG_ M2I_Byrack_Enable_IMM16_19 : 24|2@1+ (1,0) [0|3] ""  IMM
 SG_ M2I_Byrack_ReVeEnable_IMM16_19 : 26|2@1+ (1,0) [0|3] ""  IMM
 SG_ Reserved_19 : 28|4@1+ (1,0) [0|15] ""  IMM
 SG_ M2I_Byrack_IsPostTm_IMM16_19 : 32|8@1+ (0.01,0) [0|2.55] "s"  IMM
 SG_ M2I_Byrack_SysABStTm_IMM16_19 : 40|16@1+ (0.01,0) [0|655.35] "s"  IMM
 SG_ Reserved_19 : 56|8@1+ (1,0) [0|255] ""  IMM

BO_ 2332111012 M2I_Byrack_SUMDATA16__20: 8 MBMU
 SG_ CRC_M2I_Byrack_IMM16_20 : 0|8@1+ (1,0) [0|255] ""  IMM
 SG_ M2I_Byrack_HVS_IMM16_20 : 8|16@1+ (0.1,0) [0|6553.5] "v"  IMM
 SG_ M2I_Byrack_Enable_IMM16_20 : 24|2@1+ (1,0) [0|3] ""  IMM
 SG_ M2I_Byrack_ReVeEnable_IMM16_20 : 26|2@1+ (1,0) [0|3] ""  IMM
 SG_ Reserved_20 : 28|4@1+ (1,0) [0|15] ""  IMM
 SG_ M2I_Byrack_IsPostTm_IMM16_20 : 32|8@1+ (0.01,0) [0|2.55] "s"  IMM
 SG_ M2I_Byrack_SysABStTm_IMM16_20 : 40|16@1+ (0.01,0) [0|655.35] "s"  IMM
 SG_ Reserved_20 : 56|8@1+ (1,0) [0|255] ""  IMM

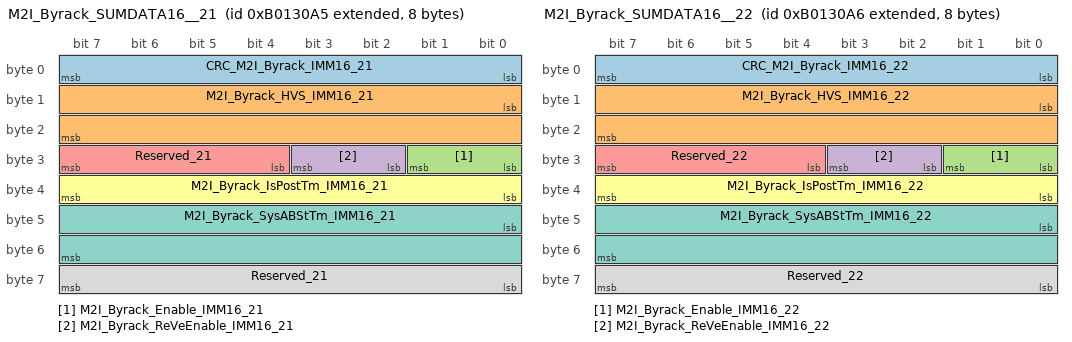
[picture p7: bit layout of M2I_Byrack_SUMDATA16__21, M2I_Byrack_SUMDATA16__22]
BO_ 2332111013 M2I_Byrack_SUMDATA16__21: 8 MBMU
 SG_ CRC_M2I_Byrack_IMM16_21 : 0|8@1+ (1,0) [0|255] ""  IMM
 SG_ M2I_Byrack_HVS_IMM16_21 : 8|16@1+ (0.1,0) [0|6553.5] "v"  IMM
 SG_ M2I_Byrack_Enable_IMM16_21 : 24|2@1+ (1,0) [0|3] ""  IMM
 SG_ M2I_Byrack_ReVeEnable_IMM16_21 : 26|2@1+ (1,0) [0|3] ""  IMM
 SG_ Reserved_21 : 28|4@1+ (1,0) [0|15] ""  IMM
 SG_ M2I_Byrack_IsPostTm_IMM16_21 : 32|8@1+ (0.01,0) [0|2.55] "s"  IMM
 SG_ M2I_Byrack_SysABStTm_IMM16_21 : 40|16@1+ (0.01,0) [0|655.35] "s"  IMM
 SG_ Reserved_21 : 56|8@1+ (1,0) [0|255] ""  IMM

BO_ 2332111014 M2I_Byrack_SUMDATA16__22: 8 MBMU
 SG_ CRC_M2I_Byrack_IMM16_22 : 0|8@1+ (1,0) [0|255] ""  IMM
 SG_ M2I_Byrack_HVS_IMM16_22 : 8|16@1+ (0.1,0) [0|6553.5] "v"  IMM
 SG_ M2I_Byrack_Enable_IMM16_22 : 24|2@1+ (1,0) [0|3] ""  IMM
 SG_ M2I_Byrack_ReVeEnable_IMM16_22 : 26|2@1+ (1,0) [0|3] ""  IMM
 SG_ Reserved_22 : 28|4@1+ (1,0) [0|15] ""  IMM
 SG_ M2I_Byrack_IsPostTm_IMM16_22 : 32|8@1+ (0.01,0) [0|2.55] "s"  IMM
 SG_ M2I_Byrack_SysABStTm_IMM16_22 : 40|16@1+ (0.01,0) [0|655.35] "s"  IMM
 SG_ Reserved_22 : 56|8@1+ (1,0) [0|255] ""  IMM

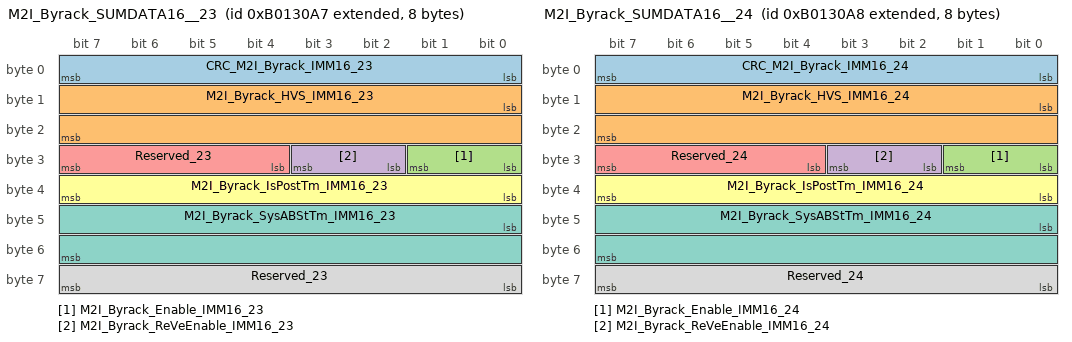
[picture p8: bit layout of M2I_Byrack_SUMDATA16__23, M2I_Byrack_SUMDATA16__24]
BO_ 2332111015 M2I_Byrack_SUMDATA16__23: 8 MBMU
 SG_ CRC_M2I_Byrack_IMM16_23 : 0|8@1+ (1,0) [0|255] ""  IMM
 SG_ M2I_Byrack_HVS_IMM16_23 : 8|16@1+ (0.1,0) [0|6553.5] "v"  IMM
 SG_ M2I_Byrack_Enable_IMM16_23 : 24|2@1+ (1,0) [0|3] ""  IMM
 SG_ M2I_Byrack_ReVeEnable_IMM16_23 : 26|2@1+ (1,0) [0|3] ""  IMM
 SG_ Reserved_23 : 28|4@1+ (1,0) [0|15] ""  IMM
 SG_ M2I_Byrack_IsPostTm_IMM16_23 : 32|8@1+ (0.01,0) [0|2.55] "s"  IMM
 SG_ M2I_Byrack_SysABStTm_IMM16_23 : 40|16@1+ (0.01,0) [0|655.35] "s"  IMM
 SG_ Reserved_23 : 56|8@1+ (1,0) [0|255] ""  IMM

BO_ 2332111016 M2I_Byrack_SUMDATA16__24: 8 MBMU
 SG_ CRC_M2I_Byrack_IMM16_24 : 0|8@1+ (1,0) [0|255] ""  IMM
 SG_ M2I_Byrack_HVS_IMM16_24 : 8|16@1+ (0.1,0) [0|6553.5] "v"  IMM
 SG_ M2I_Byrack_Enable_IMM16_24 : 24|2@1+ (1,0) [0|3] ""  IMM
 SG_ M2I_Byrack_ReVeEnable_IMM16_24 : 26|2@1+ (1,0) [0|3] ""  IMM
 SG_ Reserved_24 : 28|4@1+ (1,0) [0|15] ""  IMM
 SG_ M2I_Byrack_IsPostTm_IMM16_24 : 32|8@1+ (0.01,0) [0|2.55] "s"  IMM
 SG_ M2I_Byrack_SysABStTm_IMM16_24 : 40|16@1+ (0.01,0) [0|655.35] "s"  IMM
 SG_ Reserved_24 : 56|8@1+ (1,0) [0|255] ""  IMM

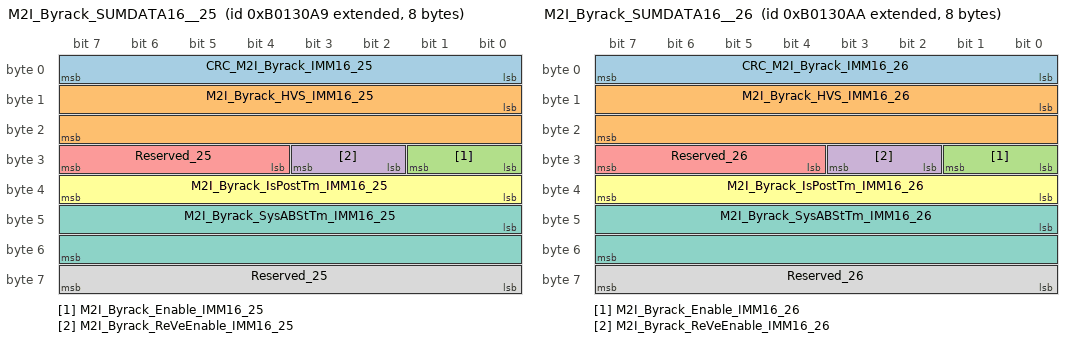
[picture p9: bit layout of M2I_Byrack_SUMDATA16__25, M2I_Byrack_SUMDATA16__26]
BO_ 2332111017 M2I_Byrack_SUMDATA16__25: 8 MBMU
 SG_ CRC_M2I_Byrack_IMM16_25 : 0|8@1+ (1,0) [0|255] ""  IMM
 SG_ M2I_Byrack_HVS_IMM16_25 : 8|16@1+ (0.1,0) [0|6553.5] "v"  IMM
 SG_ M2I_Byrack_Enable_IMM16_25 : 24|2@1+ (1,0) [0|3] ""  IMM
 SG_ M2I_Byrack_ReVeEnable_IMM16_25 : 26|2@1+ (1,0) [0|3] ""  IMM
 SG_ Reserved_25 : 28|4@1+ (1,0) [0|15] ""  IMM
 SG_ M2I_Byrack_IsPostTm_IMM16_25 : 32|8@1+ (0.01,0) [0|2.55] "s"  IMM
 SG_ M2I_Byrack_SysABStTm_IMM16_25 : 40|16@1+ (0.01,0) [0|655.35] "s"  IMM
 SG_ Reserved_25 : 56|8@1+ (1,0) [0|255] ""  IMM

BO_ 2332111018 M2I_Byrack_SUMDATA16__26: 8 MBMU
 SG_ CRC_M2I_Byrack_IMM16_26 : 0|8@1+ (1,0) [0|255] ""  IMM
 SG_ M2I_Byrack_HVS_IMM16_26 : 8|16@1+ (0.1,0) [0|6553.5] "v"  IMM
 SG_ M2I_Byrack_Enable_IMM16_26 : 24|2@1+ (1,0) [0|3] ""  IMM
 SG_ M2I_Byrack_ReVeEnable_IMM16_26 : 26|2@1+ (1,0) [0|3] ""  IMM
 SG_ Reserved_26 : 28|4@1+ (1,0) [0|15] ""  IMM
 SG_ M2I_Byrack_IsPostTm_IMM16_26 : 32|8@1+ (0.01,0) [0|2.55] "s"  IMM
 SG_ M2I_Byrack_SysABStTm_IMM16_26 : 40|16@1+ (0.01,0) [0|655.35] "s"  IMM
 SG_ Reserved_26 : 56|8@1+ (1,0) [0|255] ""  IMM

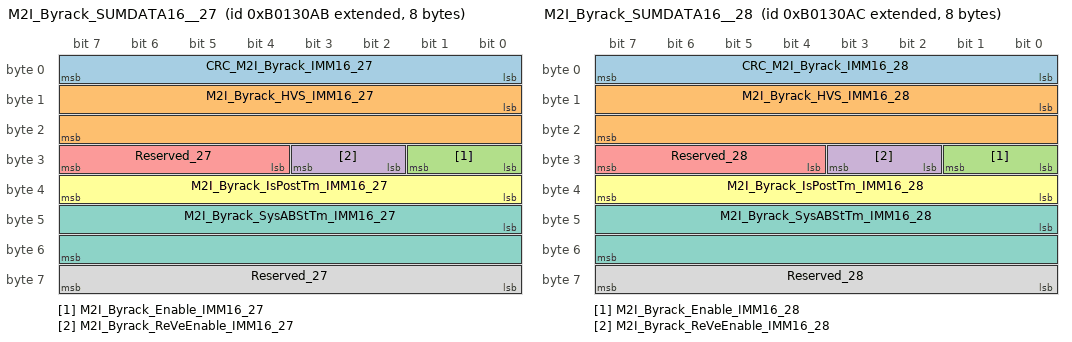
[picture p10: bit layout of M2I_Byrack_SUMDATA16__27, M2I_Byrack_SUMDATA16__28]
BO_ 2332111019 M2I_Byrack_SUMDATA16__27: 8 MBMU
 SG_ CRC_M2I_Byrack_IMM16_27 : 0|8@1+ (1,0) [0|255] ""  IMM
 SG_ M2I_Byrack_HVS_IMM16_27 : 8|16@1+ (0.1,0) [0|6553.5] "v"  IMM
 SG_ M2I_Byrack_Enable_IMM16_27 : 24|2@1+ (1,0) [0|3] ""  IMM
 SG_ M2I_Byrack_ReVeEnable_IMM16_27 : 26|2@1+ (1,0) [0|3] ""  IMM
 SG_ Reserved_27 : 28|4@1+ (1,0) [0|15] ""  IMM
 SG_ M2I_Byrack_IsPostTm_IMM16_27 : 32|8@1+ (0.01,0) [0|2.55] "s"  IMM
 SG_ M2I_Byrack_SysABStTm_IMM16_27 : 40|16@1+ (0.01,0) [0|655.35] "s"  IMM
 SG_ Reserved_27 : 56|8@1+ (1,0) [0|255] ""  IMM

BO_ 2332111020 M2I_Byrack_SUMDATA16__28: 8 MBMU
 SG_ CRC_M2I_Byrack_IMM16_28 : 0|8@1+ (1,0) [0|255] ""  IMM
 SG_ M2I_Byrack_HVS_IMM16_28 : 8|16@1+ (0.1,0) [0|6553.5] "v"  IMM
 SG_ M2I_Byrack_Enable_IMM16_28 : 24|2@1+ (1,0) [0|3] ""  IMM
 SG_ M2I_Byrack_ReVeEnable_IMM16_28 : 26|2@1+ (1,0) [0|3] ""  IMM
 SG_ Reserved_28 : 28|4@1+ (1,0) [0|15] ""  IMM
 SG_ M2I_Byrack_IsPostTm_IMM16_28 : 32|8@1+ (0.01,0) [0|2.55] "s"  IMM
 SG_ M2I_Byrack_SysABStTm_IMM16_28 : 40|16@1+ (0.01,0) [0|655.35] "s"  IMM
 SG_ Reserved_28 : 56|8@1+ (1,0) [0|255] ""  IMM

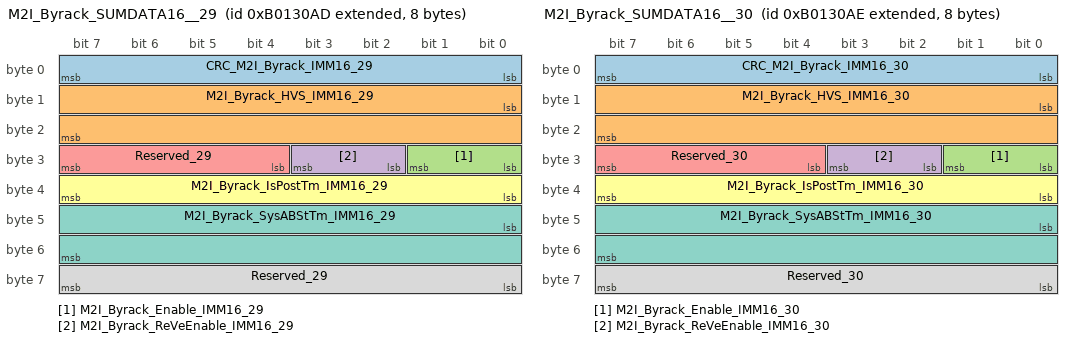
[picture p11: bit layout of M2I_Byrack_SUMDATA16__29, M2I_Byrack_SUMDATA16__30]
BO_ 2332111021 M2I_Byrack_SUMDATA16__29: 8 MBMU
 SG_ CRC_M2I_Byrack_IMM16_29 : 0|8@1+ (1,0) [0|255] ""  IMM
 SG_ M2I_Byrack_HVS_IMM16_29 : 8|16@1+ (0.1,0) [0|6553.5] "v"  IMM
 SG_ M2I_Byrack_Enable_IMM16_29 : 24|2@1+ (1,0) [0|3] ""  IMM
 SG_ M2I_Byrack_ReVeEnable_IMM16_29 : 26|2@1+ (1,0) [0|3] ""  IMM
 SG_ Reserved_29 : 28|4@1+ (1,0) [0|15] ""  IMM
 SG_ M2I_Byrack_IsPostTm_IMM16_29 : 32|8@1+ (0.01,0) [0|2.55] "s"  IMM
 SG_ M2I_Byrack_SysABStTm_IMM16_29 : 40|16@1+ (0.01,0) [0|655.35] "s"  IMM
 SG_ Reserved_29 : 56|8@1+ (1,0) [0|255] ""  IMM

BO_ 2332111022 M2I_Byrack_SUMDATA16__30: 8 MBMU
 SG_ CRC_M2I_Byrack_IMM16_30 : 0|8@1+ (1,0) [0|255] ""  IMM
 SG_ M2I_Byrack_HVS_IMM16_30 : 8|16@1+ (0.1,0) [0|6553.5] "v"  IMM
 SG_ M2I_Byrack_Enable_IMM16_30 : 24|2@1+ (1,0) [0|3] ""  IMM
 SG_ M2I_Byrack_ReVeEnable_IMM16_30 : 26|2@1+ (1,0) [0|3] ""  IMM
 SG_ Reserved_30 : 28|4@1+ (1,0) [0|15] ""  IMM
 SG_ M2I_Byrack_IsPostTm_IMM16_30 : 32|8@1+ (0.01,0) [0|2.55] "s"  IMM
 SG_ M2I_Byrack_SysABStTm_IMM16_30 : 40|16@1+ (0.01,0) [0|655.35] "s"  IMM
 SG_ Reserved_30 : 56|8@1+ (1,0) [0|255] ""  IMM

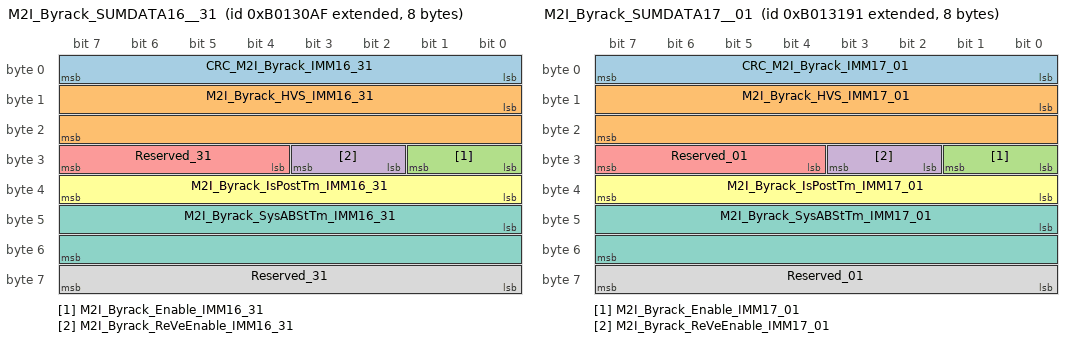
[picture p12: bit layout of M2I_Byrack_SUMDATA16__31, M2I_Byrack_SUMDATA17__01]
BO_ 2332111023 M2I_Byrack_SUMDATA16__31: 8 MBMU
 SG_ CRC_M2I_Byrack_IMM16_31 : 0|8@1+ (1,0) [0|255] ""  IMM
 SG_ M2I_Byrack_HVS_IMM16_31 : 8|16@1+ (0.1,0) [0|6553.5] "v"  IMM
 SG_ M2I_Byrack_Enable_IMM16_31 : 24|2@1+ (1,0) [0|3] ""  IMM
 SG_ M2I_Byrack_ReVeEnable_IMM16_31 : 26|2@1+ (1,0) [0|3] ""  IMM
 SG_ Reserved_31 : 28|4@1+ (1,0) [0|15] ""  IMM
 SG_ M2I_Byrack_IsPostTm_IMM16_31 : 32|8@1+ (0.01,0) [0|2.55] "s"  IMM
 SG_ M2I_Byrack_SysABStTm_IMM16_31 : 40|16@1+ (0.01,0) [0|655.35] "s"  IMM
 SG_ Reserved_31 : 56|8@1+ (1,0) [0|255] ""  IMM

BO_ 2332111249 M2I_Byrack_SUMDATA17__01: 8 MBMU
 SG_ CRC_M2I_Byrack_IMM17_01 : 0|8@1+ (1,0) [0|255] ""  IMM
 SG_ M2I_Byrack_HVS_IMM17_01 : 8|16@1+ (0.1,0) [0|6553.5] "v"  IMM
 SG_ M2I_Byrack_Enable_IMM17_01 : 24|2@1+ (1,0) [0|3] ""  IMM
 SG_ M2I_Byrack_ReVeEnable_IMM17_01 : 26|2@1+ (1,0) [0|3] ""  IMM
 SG_ Reserved_01 : 28|4@1+ (1,0) [0|15] ""  IMM
 SG_ M2I_Byrack_IsPostTm_IMM17_01 : 32|8@1+ (0.01,0) [0|2.55] "s"  IMM
 SG_ M2I_Byrack_SysABStTm_IMM17_01 : 40|16@1+ (0.01,0) [0|655.35] "s"  IMM
 SG_ Reserved_01 : 56|8@1+ (1,0) [0|255] ""  IMM

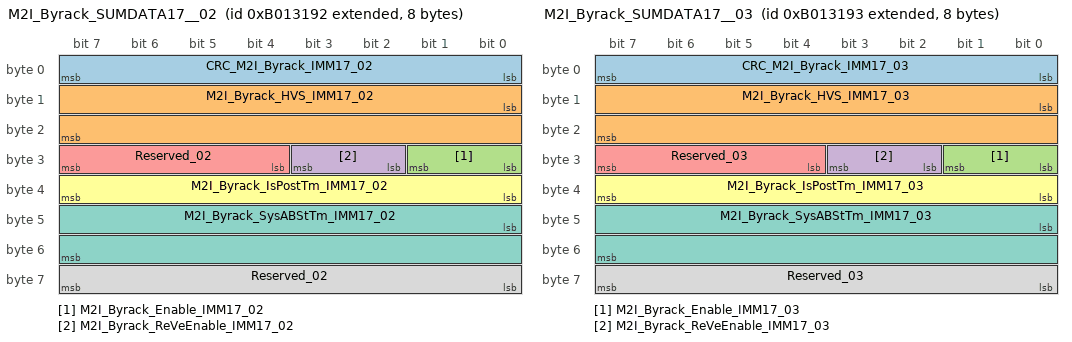
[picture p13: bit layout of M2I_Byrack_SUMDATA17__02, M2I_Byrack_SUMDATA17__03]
BO_ 2332111250 M2I_Byrack_SUMDATA17__02: 8 MBMU
 SG_ CRC_M2I_Byrack_IMM17_02 : 0|8@1+ (1,0) [0|255] ""  IMM
 SG_ M2I_Byrack_HVS_IMM17_02 : 8|16@1+ (0.1,0) [0|6553.5] "v"  IMM
 SG_ M2I_Byrack_Enable_IMM17_02 : 24|2@1+ (1,0) [0|3] ""  IMM
 SG_ M2I_Byrack_ReVeEnable_IMM17_02 : 26|2@1+ (1,0) [0|3] ""  IMM
 SG_ Reserved_02 : 28|4@1+ (1,0) [0|15] ""  IMM
 SG_ M2I_Byrack_IsPostTm_IMM17_02 : 32|8@1+ (0.01,0) [0|2.55] "s"  IMM
 SG_ M2I_Byrack_SysABStTm_IMM17_02 : 40|16@1+ (0.01,0) [0|655.35] "s"  IMM
 SG_ Reserved_02 : 56|8@1+ (1,0) [0|255] ""  IMM

BO_ 2332111251 M2I_Byrack_SUMDATA17__03: 8 MBMU
 SG_ CRC_M2I_Byrack_IMM17_03 : 0|8@1+ (1,0) [0|255] ""  IMM
 SG_ M2I_Byrack_HVS_IMM17_03 : 8|16@1+ (0.1,0) [0|6553.5] "v"  IMM
 SG_ M2I_Byrack_Enable_IMM17_03 : 24|2@1+ (1,0) [0|3] ""  IMM
 SG_ M2I_Byrack_ReVeEnable_IMM17_03 : 26|2@1+ (1,0) [0|3] ""  IMM
 SG_ Reserved_03 : 28|4@1+ (1,0) [0|15] ""  IMM
 SG_ M2I_Byrack_IsPostTm_IMM17_03 : 32|8@1+ (0.01,0) [0|2.55] "s"  IMM
 SG_ M2I_Byrack_SysABStTm_IMM17_03 : 40|16@1+ (0.01,0) [0|655.35] "s"  IMM
 SG_ Reserved_03 : 56|8@1+ (1,0) [0|255] ""  IMM

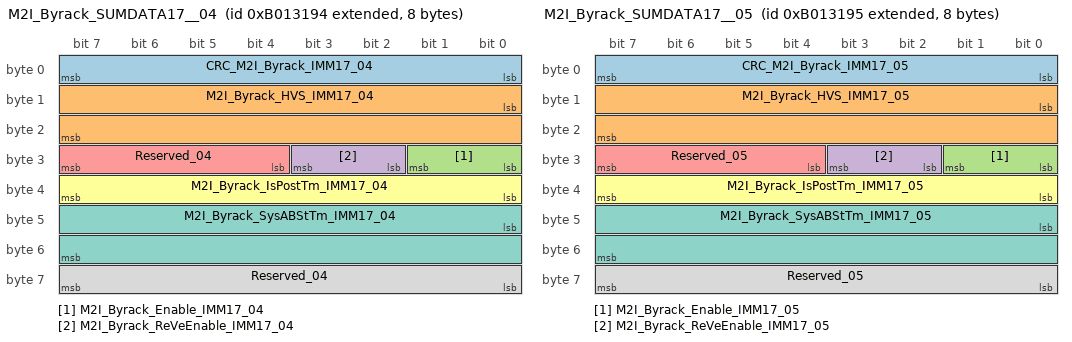
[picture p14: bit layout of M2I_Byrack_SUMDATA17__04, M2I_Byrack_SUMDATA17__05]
BO_ 2332111252 M2I_Byrack_SUMDATA17__04: 8 MBMU
 SG_ CRC_M2I_Byrack_IMM17_04 : 0|8@1+ (1,0) [0|255] ""  IMM
 SG_ M2I_Byrack_HVS_IMM17_04 : 8|16@1+ (0.1,0) [0|6553.5] "v"  IMM
 SG_ M2I_Byrack_Enable_IMM17_04 : 24|2@1+ (1,0) [0|3] ""  IMM
 SG_ M2I_Byrack_ReVeEnable_IMM17_04 : 26|2@1+ (1,0) [0|3] ""  IMM
 SG_ Reserved_04 : 28|4@1+ (1,0) [0|15] ""  IMM
 SG_ M2I_Byrack_IsPostTm_IMM17_04 : 32|8@1+ (0.01,0) [0|2.55] "s"  IMM
 SG_ M2I_Byrack_SysABStTm_IMM17_04 : 40|16@1+ (0.01,0) [0|655.35] "s"  IMM
 SG_ Reserved_04 : 56|8@1+ (1,0) [0|255] ""  IMM

BO_ 2332111253 M2I_Byrack_SUMDATA17__05: 8 MBMU
 SG_ CRC_M2I_Byrack_IMM17_05 : 0|8@1+ (1,0) [0|255] ""  IMM
 SG_ M2I_Byrack_HVS_IMM17_05 : 8|16@1+ (0.1,0) [0|6553.5] "v"  IMM
 SG_ M2I_Byrack_Enable_IMM17_05 : 24|2@1+ (1,0) [0|3] ""  IMM
 SG_ M2I_Byrack_ReVeEnable_IMM17_05 : 26|2@1+ (1,0) [0|3] ""  IMM
 SG_ Reserved_05 : 28|4@1+ (1,0) [0|15] ""  IMM
 SG_ M2I_Byrack_IsPostTm_IMM17_05 : 32|8@1+ (0.01,0) [0|2.55] "s"  IMM
 SG_ M2I_Byrack_SysABStTm_IMM17_05 : 40|16@1+ (0.01,0) [0|655.35] "s"  IMM
 SG_ Reserved_05 : 56|8@1+ (1,0) [0|255] ""  IMM

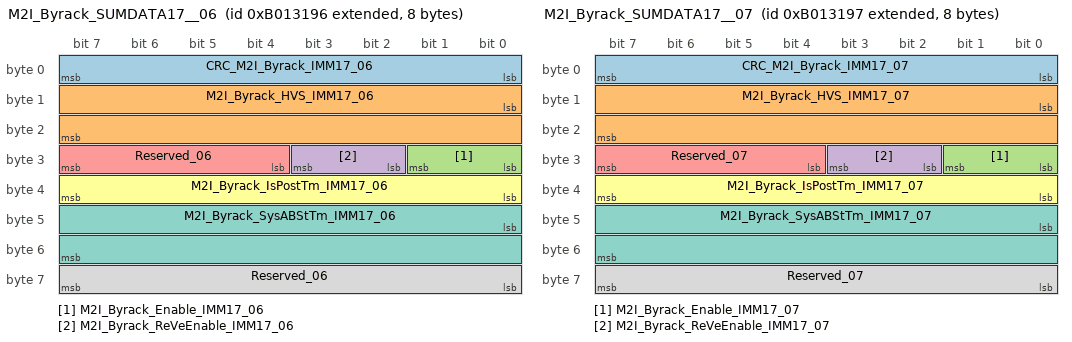
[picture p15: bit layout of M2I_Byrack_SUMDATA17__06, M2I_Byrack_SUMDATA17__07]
BO_ 2332111254 M2I_Byrack_SUMDATA17__06: 8 MBMU
 SG_ CRC_M2I_Byrack_IMM17_06 : 0|8@1+ (1,0) [0|255] ""  IMM
 SG_ M2I_Byrack_HVS_IMM17_06 : 8|16@1+ (0.1,0) [0|6553.5] "v"  IMM
 SG_ M2I_Byrack_Enable_IMM17_06 : 24|2@1+ (1,0) [0|3] ""  IMM
 SG_ M2I_Byrack_ReVeEnable_IMM17_06 : 26|2@1+ (1,0) [0|3] ""  IMM
 SG_ Reserved_06 : 28|4@1+ (1,0) [0|15] ""  IMM
 SG_ M2I_Byrack_IsPostTm_IMM17_06 : 32|8@1+ (0.01,0) [0|2.55] "s"  IMM
 SG_ M2I_Byrack_SysABStTm_IMM17_06 : 40|16@1+ (0.01,0) [0|655.35] "s"  IMM
 SG_ Reserved_06 : 56|8@1+ (1,0) [0|255] ""  IMM

BO_ 2332111255 M2I_Byrack_SUMDATA17__07: 8 MBMU
 SG_ CRC_M2I_Byrack_IMM17_07 : 0|8@1+ (1,0) [0|255] ""  IMM
 SG_ M2I_Byrack_HVS_IMM17_07 : 8|16@1+ (0.1,0) [0|6553.5] "v"  IMM
 SG_ M2I_Byrack_Enable_IMM17_07 : 24|2@1+ (1,0) [0|3] ""  IMM
 SG_ M2I_Byrack_ReVeEnable_IMM17_07 : 26|2@1+ (1,0) [0|3] ""  IMM
 SG_ Reserved_07 : 28|4@1+ (1,0) [0|15] ""  IMM
 SG_ M2I_Byrack_IsPostTm_IMM17_07 : 32|8@1+ (0.01,0) [0|2.55] "s"  IMM
 SG_ M2I_Byrack_SysABStTm_IMM17_07 : 40|16@1+ (0.01,0) [0|655.35] "s"  IMM
 SG_ Reserved_07 : 56|8@1+ (1,0) [0|255] ""  IMM

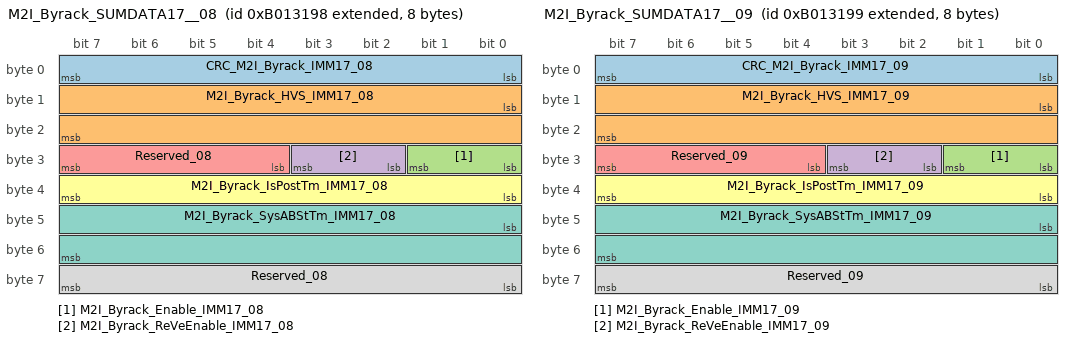
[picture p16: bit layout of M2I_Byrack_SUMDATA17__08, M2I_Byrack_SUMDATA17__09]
BO_ 2332111256 M2I_Byrack_SUMDATA17__08: 8 MBMU
 SG_ CRC_M2I_Byrack_IMM17_08 : 0|8@1+ (1,0) [0|255] ""  IMM
 SG_ M2I_Byrack_HVS_IMM17_08 : 8|16@1+ (0.1,0) [0|6553.5] "v"  IMM
 SG_ M2I_Byrack_Enable_IMM17_08 : 24|2@1+ (1,0) [0|3] ""  IMM
 SG_ M2I_Byrack_ReVeEnable_IMM17_08 : 26|2@1+ (1,0) [0|3] ""  IMM
 SG_ Reserved_08 : 28|4@1+ (1,0) [0|15] ""  IMM
 SG_ M2I_Byrack_IsPostTm_IMM17_08 : 32|8@1+ (0.01,0) [0|2.55] "s"  IMM
 SG_ M2I_Byrack_SysABStTm_IMM17_08 : 40|16@1+ (0.01,0) [0|655.35] "s"  IMM
 SG_ Reserved_08 : 56|8@1+ (1,0) [0|255] ""  IMM

BO_ 2332111257 M2I_Byrack_SUMDATA17__09: 8 MBMU
 SG_ CRC_M2I_Byrack_IMM17_09 : 0|8@1+ (1,0) [0|255] ""  IMM
 SG_ M2I_Byrack_HVS_IMM17_09 : 8|16@1+ (0.1,0) [0|6553.5] "v"  IMM
 SG_ M2I_Byrack_Enable_IMM17_09 : 24|2@1+ (1,0) [0|3] ""  IMM
 SG_ M2I_Byrack_ReVeEnable_IMM17_09 : 26|2@1+ (1,0) [0|3] ""  IMM
 SG_ Reserved_09 : 28|4@1+ (1,0) [0|15] ""  IMM
 SG_ M2I_Byrack_IsPostTm_IMM17_09 : 32|8@1+ (0.01,0) [0|2.55] "s"  IMM
 SG_ M2I_Byrack_SysABStTm_IMM17_09 : 40|16@1+ (0.01,0) [0|655.35] "s"  IMM
 SG_ Reserved_09 : 56|8@1+ (1,0) [0|255] ""  IMM

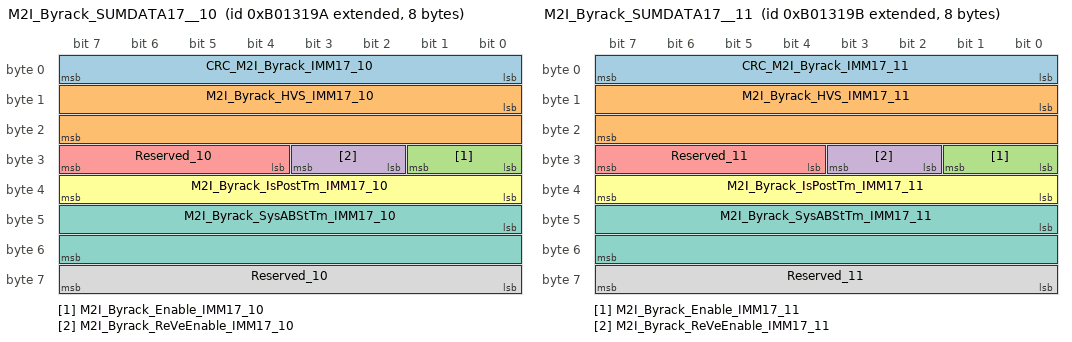
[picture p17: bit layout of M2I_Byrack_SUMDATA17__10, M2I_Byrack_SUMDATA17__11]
BO_ 2332111258 M2I_Byrack_SUMDATA17__10: 8 MBMU
 SG_ CRC_M2I_Byrack_IMM17_10 : 0|8@1+ (1,0) [0|255] ""  IMM
 SG_ M2I_Byrack_HVS_IMM17_10 : 8|16@1+ (0.1,0) [0|6553.5] "v"  IMM
 SG_ M2I_Byrack_Enable_IMM17_10 : 24|2@1+ (1,0) [0|3] ""  IMM
 SG_ M2I_Byrack_ReVeEnable_IMM17_10 : 26|2@1+ (1,0) [0|3] ""  IMM
 SG_ Reserved_10 : 28|4@1+ (1,0) [0|15] ""  IMM
 SG_ M2I_Byrack_IsPostTm_IMM17_10 : 32|8@1+ (0.01,0) [0|2.55] "s"  IMM
 SG_ M2I_Byrack_SysABStTm_IMM17_10 : 40|16@1+ (0.01,0) [0|655.35] "s"  IMM
 SG_ Reserved_10 : 56|8@1+ (1,0) [0|255] ""  IMM

BO_ 2332111259 M2I_Byrack_SUMDATA17__11: 8 MBMU
 SG_ CRC_M2I_Byrack_IMM17_11 : 0|8@1+ (1,0) [0|255] ""  IMM
 SG_ M2I_Byrack_HVS_IMM17_11 : 8|16@1+ (0.1,0) [0|6553.5] "v"  IMM
 SG_ M2I_Byrack_Enable_IMM17_11 : 24|2@1+ (1,0) [0|3] ""  IMM
 SG_ M2I_Byrack_ReVeEnable_IMM17_11 : 26|2@1+ (1,0) [0|3] ""  IMM
 SG_ Reserved_11 : 28|4@1+ (1,0) [0|15] ""  IMM
 SG_ M2I_Byrack_IsPostTm_IMM17_11 : 32|8@1+ (0.01,0) [0|2.55] "s"  IMM
 SG_ M2I_Byrack_SysABStTm_IMM17_11 : 40|16@1+ (0.01,0) [0|655.35] "s"  IMM
 SG_ Reserved_11 : 56|8@1+ (1,0) [0|255] ""  IMM

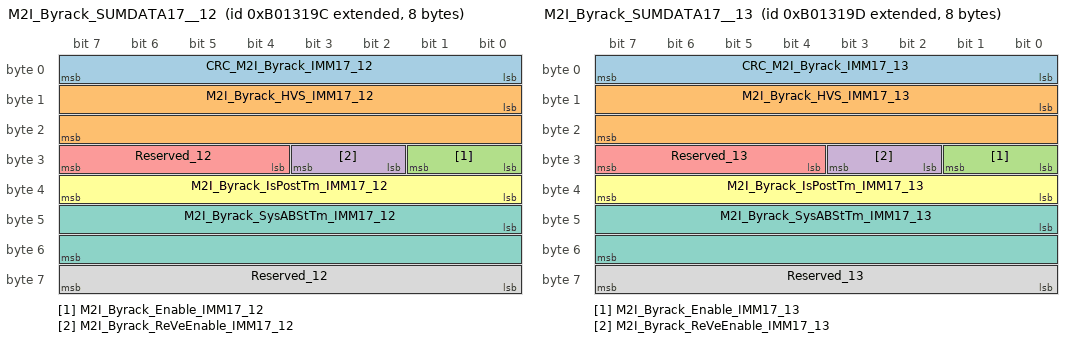
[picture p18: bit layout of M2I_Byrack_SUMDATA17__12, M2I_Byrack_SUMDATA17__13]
BO_ 2332111260 M2I_Byrack_SUMDATA17__12: 8 MBMU
 SG_ CRC_M2I_Byrack_IMM17_12 : 0|8@1+ (1,0) [0|255] ""  IMM
 SG_ M2I_Byrack_HVS_IMM17_12 : 8|16@1+ (0.1,0) [0|6553.5] "v"  IMM
 SG_ M2I_Byrack_Enable_IMM17_12 : 24|2@1+ (1,0) [0|3] ""  IMM
 SG_ M2I_Byrack_ReVeEnable_IMM17_12 : 26|2@1+ (1,0) [0|3] ""  IMM
 SG_ Reserved_12 : 28|4@1+ (1,0) [0|15] ""  IMM
 SG_ M2I_Byrack_IsPostTm_IMM17_12 : 32|8@1+ (0.01,0) [0|2.55] "s"  IMM
 SG_ M2I_Byrack_SysABStTm_IMM17_12 : 40|16@1+ (0.01,0) [0|655.35] "s"  IMM
 SG_ Reserved_12 : 56|8@1+ (1,0) [0|255] ""  IMM

BO_ 2332111261 M2I_Byrack_SUMDATA17__13: 8 MBMU
 SG_ CRC_M2I_Byrack_IMM17_13 : 0|8@1+ (1,0) [0|255] ""  IMM
 SG_ M2I_Byrack_HVS_IMM17_13 : 8|16@1+ (0.1,0) [0|6553.5] "v"  IMM
 SG_ M2I_Byrack_Enable_IMM17_13 : 24|2@1+ (1,0) [0|3] ""  IMM
 SG_ M2I_Byrack_ReVeEnable_IMM17_13 : 26|2@1+ (1,0) [0|3] ""  IMM
 SG_ Reserved_13 : 28|4@1+ (1,0) [0|15] ""  IMM
 SG_ M2I_Byrack_IsPostTm_IMM17_13 : 32|8@1+ (0.01,0) [0|2.55] "s"  IMM
 SG_ M2I_Byrack_SysABStTm_IMM17_13 : 40|16@1+ (0.01,0) [0|655.35] "s"  IMM
 SG_ Reserved_13 : 56|8@1+ (1,0) [0|255] ""  IMM

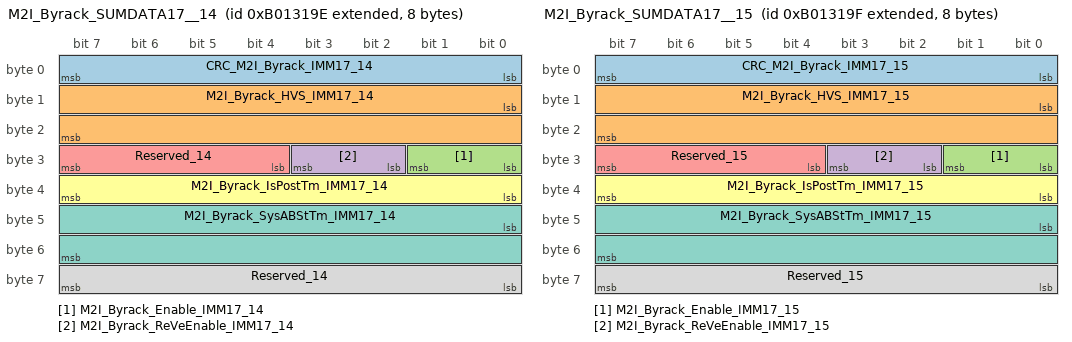
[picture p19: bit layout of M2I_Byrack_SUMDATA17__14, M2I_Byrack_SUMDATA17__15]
BO_ 2332111262 M2I_Byrack_SUMDATA17__14: 8 MBMU
 SG_ CRC_M2I_Byrack_IMM17_14 : 0|8@1+ (1,0) [0|255] ""  IMM
 SG_ M2I_Byrack_HVS_IMM17_14 : 8|16@1+ (0.1,0) [0|6553.5] "v"  IMM
 SG_ M2I_Byrack_Enable_IMM17_14 : 24|2@1+ (1,0) [0|3] ""  IMM
 SG_ M2I_Byrack_ReVeEnable_IMM17_14 : 26|2@1+ (1,0) [0|3] ""  IMM
 SG_ Reserved_14 : 28|4@1+ (1,0) [0|15] ""  IMM
 SG_ M2I_Byrack_IsPostTm_IMM17_14 : 32|8@1+ (0.01,0) [0|2.55] "s"  IMM
 SG_ M2I_Byrack_SysABStTm_IMM17_14 : 40|16@1+ (0.01,0) [0|655.35] "s"  IMM
 SG_ Reserved_14 : 56|8@1+ (1,0) [0|255] ""  IMM

BO_ 2332111263 M2I_Byrack_SUMDATA17__15: 8 MBMU
 SG_ CRC_M2I_Byrack_IMM17_15 : 0|8@1+ (1,0) [0|255] ""  IMM
 SG_ M2I_Byrack_HVS_IMM17_15 : 8|16@1+ (0.1,0) [0|6553.5] "v"  IMM
 SG_ M2I_Byrack_Enable_IMM17_15 : 24|2@1+ (1,0) [0|3] ""  IMM
 SG_ M2I_Byrack_ReVeEnable_IMM17_15 : 26|2@1+ (1,0) [0|3] ""  IMM
 SG_ Reserved_15 : 28|4@1+ (1,0) [0|15] ""  IMM
 SG_ M2I_Byrack_IsPostTm_IMM17_15 : 32|8@1+ (0.01,0) [0|2.55] "s"  IMM
 SG_ M2I_Byrack_SysABStTm_IMM17_15 : 40|16@1+ (0.01,0) [0|655.35] "s"  IMM
 SG_ Reserved_15 : 56|8@1+ (1,0) [0|255] ""  IMM

BO_ 2332111264 M2I_Byrack_SUMDATA17__16: 8 MBMU
 SG_ CRC_M2I_Byrack_IMM17_16 : 0|8@1+ (1,0) [0|255] ""  IMM
 SG_ M2I_Byrack_HVS_IMM17_16 : 8|16@1+ (0.1,0) [0|6553.5] "v"  IMM
 SG_ M2I_Byrack_Enable_IMM17_16 : 24|2@1+ (1,0) [0|3] ""  IMM
 SG_ M2I_Byrack_ReVeEnable_IMM17_16 : 26|2@1+ (1,0) [0|3] ""  IMM
 SG_ Reserved_16 : 28|4@1+ (1,0) [0|15] ""  IMM
 SG_ M2I_Byrack_IsPostTm_IMM17_16 : 32|8@1+ (0.01,0) [0|2.55] "s"  IMM
 SG_ M2I_Byrack_SysABStTm_IMM17_16 : 40|16@1+ (0.01,0) [0|655.35] "s"  IMM
 SG_ Reserved_16 : 56|8@1+ (1,0) [0|255] ""  IMM

BO_ 2332111265 M2I_Byrack_SUMDATA17__17: 8 MBMU
 SG_ CRC_M2I_Byrack_IMM17_17 : 0|8@1+ (1,0) [0|255] ""  IMM
 SG_ M2I_Byrack_HVS_IMM17_17 : 8|16@1+ (0.1,0) [0|6553.5] "v"  IMM
 SG_ M2I_Byrack_Enable_IMM17_17 : 24|2@1+ (1,0) [0|3] ""  IMM
 SG_ M2I_Byrack_ReVeEnable_IMM17_17 : 26|2@1+ (1,0) [0|3] ""  IMM
 SG_ Reserved_17 : 28|4@1+ (1,0) [0|15] ""  IMM
 SG_ M2I_Byrack_IsPostTm_IMM17_17 : 32|8@1+ (0.01,0) [0|2.55] "s"  IMM
 SG_ M2I_Byrack_SysABStTm_IMM17_17 : 40|16@1+ (0.01,0) [0|655.35] "s"  IMM
 SG_ Reserved_17 : 56|8@1+ (1,0) [0|255] ""  IMM

BO_ 2332111266 M2I_Byrack_SUMDATA17__18: 8 MBMU
 SG_ CRC_M2I_Byrack_IMM17_18 : 0|8@1+ (1,0) [0|255] ""  IMM
 SG_ M2I_Byrack_HVS_IMM17_18 : 8|16@1+ (0.1,0) [0|6553.5] "v"  IMM
 SG_ M2I_Byrack_Enable_IMM17_18 : 24|2@1+ (1,0) [0|3] ""  IMM
 SG_ M2I_Byrack_ReVeEnable_IMM17_18 : 26|2@1+ (1,0) [0|3] ""  IMM
 SG_ Reserved_18 : 28|4@1+ (1,0) [0|15] ""  IMM
 SG_ M2I_Byrack_IsPostTm_IMM17_18 : 32|8@1+ (0.01,0) [0|2.55] "s"  IMM
 SG_ M2I_Byrack_SysABStTm_IMM17_18 : 40|16@1+ (0.01,0) [0|655.35] "s"  IMM
 SG_ Reserved_18 : 56|8@1+ (1,0) [0|255] ""  IMM

BO_ 2332111267 M2I_Byrack_SUMDATA17__19: 8 MBMU
 SG_ CRC_M2I_Byrack_IMM17_19 : 0|8@1+ (1,0) [0|255] ""  IMM
 SG_ M2I_Byrack_HVS_IMM17_19 : 8|16@1+ (0.1,0) [0|6553.5] "v"  IMM
 SG_ M2I_Byrack_Enable_IMM17_19 : 24|2@1+ (1,0) [0|3] ""  IMM
 SG_ M2I_Byrack_ReVeEnable_IMM17_19 : 26|2@1+ (1,0) [0|3] ""  IMM
 SG_ Reserved_19 : 28|4@1+ (1,0) [0|15] ""  IMM
 SG_ M2I_Byrack_IsPostTm_IMM17_19 : 32|8@1+ (0.01,0) [0|2.55] "s"  IMM
 SG_ M2I_Byrack_SysABStTm_IMM17_19 : 40|16@1+ (0.01,0) [0|655.35] "s"  IMM
 SG_ Reserved_19 : 56|8@1+ (1,0) [0|255] ""  IMM

BO_ 2332111268 M2I_Byrack_SUMDATA17__20: 8 MBMU
 SG_ CRC_M2I_Byrack_IMM17_20 : 0|8@1+ (1,0) [0|255] ""  IMM
 SG_ M2I_Byrack_HVS_IMM17_20 : 8|16@1+ (0.1,0) [0|6553.5] "v"  IMM
 SG_ M2I_Byrack_Enable_IMM17_20 : 24|2@1+ (1,0) [0|3] ""  IMM
 SG_ M2I_Byrack_ReVeEnable_IMM17_20 : 26|2@1+ (1,0) [0|3] ""  IMM
 SG_ Reserved_20 : 28|4@1+ (1,0) [0|15] ""  IMM
 SG_ M2I_Byrack_IsPostTm_IMM17_20 : 32|8@1+ (0.01,0) [0|2.55] "s"  IMM
 SG_ M2I_Byrack_SysABStTm_IMM17_20 : 40|16@1+ (0.01,0) [0|655.35] "s"  IMM
 SG_ Reserved_20 : 56|8@1+ (1,0) [0|255] ""  IMM

BO_ 2332111269 M2I_Byrack_SUMDATA17__21: 8 MBMU
 SG_ CRC_M2I_Byrack_IMM17_21 : 0|8@1+ (1,0) [0|255] ""  IMM
 SG_ M2I_Byrack_HVS_IMM17_21 : 8|16@1+ (0.1,0) [0|6553.5] "v"  IMM
 SG_ M2I_Byrack_Enable_IMM17_21 : 24|2@1+ (1,0) [0|3] ""  IMM
 SG_ M2I_Byrack_ReVeEnable_IMM17_21 : 26|2@1+ (1,0) [0|3] ""  IMM
 SG_ Reserved_21 : 28|4@1+ (1,0) [0|15] ""  IMM
 SG_ M2I_Byrack_IsPostTm_IMM17_21 : 32|8@1+ (0.01,0) [0|2.55] "s"  IMM
 SG_ M2I_Byrack_SysABStTm_IMM17_21 : 40|16@1+ (0.01,0) [0|655.35] "s"  IMM
 SG_ Reserved_21 : 56|8@1+ (1,0) [0|255] ""  IMM

BO_ 2332111270 M2I_Byrack_SUMDATA17__22: 8 MBMU
 SG_ CRC_M2I_Byrack_IMM17_22 : 0|8@1+ (1,0) [0|255] ""  IMM
 SG_ M2I_Byrack_HVS_IMM17_22 : 8|16@1+ (0.1,0) [0|6553.5] "v"  IMM
 SG_ M2I_Byrack_Enable_IMM17_22 : 24|2@1+ (1,0) [0|3] ""  IMM
 SG_ M2I_Byrack_ReVeEnable_IMM17_22 : 26|2@1+ (1,0) [0|3] ""  IMM
 SG_ Reserved_22 : 28|4@1+ (1,0) [0|15] ""  IMM
 SG_ M2I_Byrack_IsPostTm_IMM17_22 : 32|8@1+ (0.01,0) [0|2.55] "s"  IMM
 SG_ M2I_Byrack_SysABStTm_IMM17_22 : 40|16@1+ (0.01,0) [0|655.35] "s"  IMM
 SG_ Reserved_22 : 56|8@1+ (1,0) [0|255] ""  IMM

BO_ 2332111271 M2I_Byrack_SUMDATA17__23: 8 MBMU
 SG_ CRC_M2I_Byrack_IMM17_23 : 0|8@1+ (1,0) [0|255] ""  IMM
 SG_ M2I_Byrack_HVS_IMM17_23 : 8|16@1+ (0.1,0) [0|6553.5] "v"  IMM
 SG_ M2I_Byrack_Enable_IMM17_23 : 24|2@1+ (1,0) [0|3] ""  IMM
 SG_ M2I_Byrack_ReVeEnable_IMM17_23 : 26|2@1+ (1,0) [0|3] ""  IMM
 SG_ Reserved_23 : 28|4@1+ (1,0) [0|15] ""  IMM
 SG_ M2I_Byrack_IsPostTm_IMM17_23 : 32|8@1+ (0.01,0) [0|2.55] "s"  IMM
 SG_ M2I_Byrack_SysABStTm_IMM17_23 : 40|16@1+ (0.01,0) [0|655.35] "s"  IMM
 SG_ Reserved_23 : 56|8@1+ (1,0) [0|255] ""  IMM

BO_ 2332111272 M2I_Byrack_SUMDATA17__24: 8 MBMU
 SG_ CRC_M2I_Byrack_IMM17_24 : 0|8@1+ (1,0) [0|255] ""  IMM
 SG_ M2I_Byrack_HVS_IMM17_24 : 8|16@1+ (0.1,0) [0|6553.5] "v"  IMM
 SG_ M2I_Byrack_Enable_IMM17_24 : 24|2@1+ (1,0) [0|3] ""  IMM
 SG_ M2I_Byrack_ReVeEnable_IMM17_24 : 26|2@1+ (1,0) [0|3] ""  IMM
 SG_ Reserved_24 : 28|4@1+ (1,0) [0|15] ""  IMM
 SG_ M2I_Byrack_IsPostTm_IMM17_24 : 32|8@1+ (0.01,0) [0|2.55] "s"  IMM
 SG_ M2I_Byrack_SysABStTm_IMM17_24 : 40|16@1+ (0.01,0) [0|655.35] "s"  IMM
 SG_ Reserved_24 : 56|8@1+ (1,0) [0|255] ""  IMM

BO_ 2332111273 M2I_Byrack_SUMDATA17__25: 8 MBMU
 SG_ CRC_M2I_Byrack_IMM17_25 : 0|8@1+ (1,0) [0|255] ""  IMM
 SG_ M2I_Byrack_HVS_IMM17_25 : 8|16@1+ (0.1,0) [0|6553.5] "v"  IMM
 SG_ M2I_Byrack_Enable_IMM17_25 : 24|2@1+ (1,0) [0|3] ""  IMM
 SG_ M2I_Byrack_ReVeEnable_IMM17_25 : 26|2@1+ (1,0) [0|3] ""  IMM
 SG_ Reserved_25 : 28|4@1+ (1,0) [0|15] ""  IMM
 SG_ M2I_Byrack_IsPostTm_IMM17_25 : 32|8@1+ (0.01,0) [0|2.55] "s"  IMM
 SG_ M2I_Byrack_SysABStTm_IMM17_25 : 40|16@1+ (0.01,0) [0|655.35] "s"  IMM
 SG_ Reserved_25 : 56|8@1+ (1,0) [0|255] ""  IMM

BO_ 2332111274 M2I_Byrack_SUMDATA17__26: 8 MBMU
 SG_ CRC_M2I_Byrack_IMM17_26 : 0|8@1+ (1,0) [0|255] ""  IMM
 SG_ M2I_Byrack_HVS_IMM17_26 : 8|16@1+ (0.1,0) [0|6553.5] "v"  IMM
 SG_ M2I_Byrack_Enable_IMM17_26 : 24|2@1+ (1,0) [0|3] ""  IMM
 SG_ M2I_Byrack_ReVeEnable_IMM17_26 : 26|2@1+ (1,0) [0|3] ""  IMM
 SG_ Reserved_26 : 28|4@1+ (1,0) [0|15] ""  IMM
 SG_ M2I_Byrack_IsPostTm_IMM17_26 : 32|8@1+ (0.01,0) [0|2.55] "s"  IMM
 SG_ M2I_Byrack_SysABStTm_IMM17_26 : 40|16@1+ (0.01,0) [0|655.35] "s"  IMM
 SG_ Reserved_26 : 56|8@1+ (1,0) [0|255] ""  IMM

BO_ 2332111275 M2I_Byrack_SUMDATA17__27: 8 MBMU
 SG_ CRC_M2I_Byrack_IMM17_27 : 0|8@1+ (1,0) [0|255] ""  IMM
 SG_ M2I_Byrack_HVS_IMM17_27 : 8|16@1+ (0.1,0) [0|6553.5] "v"  IMM
 SG_ M2I_Byrack_Enable_IMM17_27 : 24|2@1+ (1,0) [0|3] ""  IMM
 SG_ M2I_Byrack_ReVeEnable_IMM17_27 : 26|2@1+ (1,0) [0|3] ""  IMM
 SG_ Reserved_27 : 28|4@1+ (1,0) [0|15] ""  IMM
 SG_ M2I_Byrack_IsPostTm_IMM17_27 : 32|8@1+ (0.01,0) [0|2.55] "s"  IMM
 SG_ M2I_Byrack_SysABStTm_IMM17_27 : 40|16@1+ (0.01,0) [0|655.35] "s"  IMM
 SG_ Reserved_27 : 56|8@1+ (1,0) [0|255] ""  IMM

BO_ 2332111276 M2I_Byrack_SUMDATA17__28: 8 MBMU
 SG_ CRC_M2I_Byrack_IMM17_28 : 0|8@1+ (1,0) [0|255] ""  IMM
 SG_ M2I_Byrack_HVS_IMM17_28 : 8|16@1+ (0.1,0) [0|6553.5] "v"  IMM
 SG_ M2I_Byrack_Enable_IMM17_28 : 24|2@1+ (1,0) [0|3] ""  IMM
 SG_ M2I_Byrack_ReVeEnable_IMM17_28 : 26|2@1+ (1,0) [0|3] ""  IMM
 SG_ Reserved_28 : 28|4@1+ (1,0) [0|15] ""  IMM
 SG_ M2I_Byrack_IsPostTm_IMM17_28 : 32|8@1+ (0.01,0) [0|2.55] "s"  IMM
 SG_ M2I_Byrack_SysABStTm_IMM17_28 : 40|16@1+ (0.01,0) [0|655.35] "s"  IMM
 SG_ Reserved_28 : 56|8@1+ (1,0) [0|255] ""  IMM

BO_ 2332111277 M2I_Byrack_SUMDATA17__29: 8 MBMU
 SG_ CRC_M2I_Byrack_IMM17_29 : 0|8@1+ (1,0) [0|255] ""  IMM
 SG_ M2I_Byrack_HVS_IMM17_29 : 8|16@1+ (0.1,0) [0|6553.5] "v"  IMM
 SG_ M2I_Byrack_Enable_IMM17_29 : 24|2@1+ (1,0) [0|3] ""  IMM
 SG_ M2I_Byrack_ReVeEnable_IMM17_29 : 26|2@1+ (1,0) [0|3] ""  IMM
 SG_ Reserved_29 : 28|4@1+ (1,0) [0|15] ""  IMM
 SG_ M2I_Byrack_IsPostTm_IMM17_29 : 32|8@1+ (0.01,0) [0|2.55] "s"  IMM
 SG_ M2I_Byrack_SysABStTm_IMM17_29 : 40|16@1+ (0.01,0) [0|655.35] "s"  IMM
 SG_ Reserved_29 : 56|8@1+ (1,0) [0|255] ""  IMM

BO_ 2332111278 M2I_Byrack_SUMDATA17__30: 8 MBMU
 SG_ CRC_M2I_Byrack_IMM17_30 : 0|8@1+ (1,0) [0|255] ""  IMM
 SG_ M2I_Byrack_HVS_IMM17_30 : 8|16@1+ (0.1,0) [0|6553.5] "v"  IMM
 SG_ M2I_Byrack_Enable_IMM17_30 : 24|2@1+ (1,0) [0|3] ""  IMM
 SG_ M2I_Byrack_ReVeEnable_IMM17_30 : 26|2@1+ (1,0) [0|3] ""  IMM
 SG_ Reserved_30 : 28|4@1+ (1,0) [0|15] ""  IMM
 SG_ M2I_Byrack_IsPostTm_IMM17_30 : 32|8@1+ (0.01,0) [0|2.55] "s"  IMM
 SG_ M2I_Byrack_SysABStTm_IMM17_30 : 40|16@1+ (0.01,0) [0|655.35] "s"  IMM
 SG_ Reserved_30 : 56|8@1+ (1,0) [0|255] ""  IMM

BO_ 2332111279 M2I_Byrack_SUMDATA17__31: 8 MBMU
 SG_ CRC_M2I_Byrack_IMM17_31 : 0|8@1+ (1,0) [0|255] ""  IMM
 SG_ M2I_Byrack_HVS_IMM17_31 : 8|16@1+ (0.1,0) [0|6553.5] "v"  IMM
 SG_ M2I_Byrack_Enable_IMM17_31 : 24|2@1+ (1,0) [0|3] ""  IMM
 SG_ M2I_Byrack_ReVeEnable_IMM17_31 : 26|2@1+ (1,0) [0|3] ""  IMM
 SG_ Reserved_31 : 28|4@1+ (1,0) [0|15] ""  IMM
 SG_ M2I_Byrack_IsPostTm_IMM17_31 : 32|8@1+ (0.01,0) [0|2.55] "s"  IMM
 SG_ M2I_Byrack_SysABStTm_IMM17_31 : 40|16@1+ (0.01,0) [0|655.35] "s"  IMM
 SG_ Reserved_31 : 56|8@1+ (1,0) [0|255] ""  IMM

BO_ 2332111505 M2I_Byrack_SUMDATA18__01: 8 MBMU
 SG_ CRC_M2I_Byrack_IMM18_01 : 0|8@1+ (1,0) [0|255] ""  IMM
 SG_ M2I_Byrack_HVS_IMM18_01 : 8|16@1+ (0.1,0) [0|6553.5] "v"  IMM
 SG_ M2I_Byrack_Enable_IMM18_01 : 24|2@1+ (1,0) [0|3] ""  IMM
 SG_ M2I_Byrack_ReVeEnable_IMM18_01 : 26|2@1+ (1,0) [0|3] ""  IMM
 SG_ Reserved_01 : 28|4@1+ (1,0) [0|15] ""  IMM
 SG_ M2I_Byrack_IsPostTm_IMM18_01 : 32|8@1+ (0.01,0) [0|2.55] "s"  IMM
 SG_ M2I_Byrack_SysABStTm_IMM18_01 : 40|16@1+ (0.01,0) [0|655.35] "s"  IMM
 SG_ Reserved_01 : 56|8@1+ (1,0) [0|255] ""  IMM

BO_ 2332111506 M2I_Byrack_SUMDATA18__02: 8 MBMU
 SG_ CRC_M2I_Byrack_IMM18_02 : 0|8@1+ (1,0) [0|255] ""  IMM
 SG_ M2I_Byrack_HVS_IMM18_02 : 8|16@1+ (0.1,0) [0|6553.5] "v"  IMM
 SG_ M2I_Byrack_Enable_IMM18_02 : 24|2@1+ (1,0) [0|3] ""  IMM
 SG_ M2I_Byrack_ReVeEnable_IMM18_02 : 26|2@1+ (1,0) [0|3] ""  IMM
 SG_ Reserved_02 : 28|4@1+ (1,0) [0|15] ""  IMM
 SG_ M2I_Byrack_IsPostTm_IMM18_02 : 32|8@1+ (0.01,0) [0|2.55] "s"  IMM
 SG_ M2I_Byrack_SysABStTm_IMM18_02 : 40|16@1+ (0.01,0) [0|655.35] "s"  IMM
 SG_ Reserved_02 : 56|8@1+ (1,0) [0|255] ""  IMM

BO_ 2332111507 M2I_Byrack_SUMDATA18__03: 8 MBMU
 SG_ CRC_M2I_Byrack_IMM18_03 : 0|8@1+ (1,0) [0|255] ""  IMM
 SG_ M2I_Byrack_HVS_IMM18_03 : 8|16@1+ (0.1,0) [0|6553.5] "v"  IMM
 SG_ M2I_Byrack_Enable_IMM18_03 : 24|2@1+ (1,0) [0|3] ""  IMM
 SG_ M2I_Byrack_ReVeEnable_IMM18_03 : 26|2@1+ (1,0) [0|3] ""  IMM
 SG_ Reserved_03 : 28|4@1+ (1,0) [0|15] ""  IMM
 SG_ M2I_Byrack_IsPostTm_IMM18_03 : 32|8@1+ (0.01,0) [0|2.55] "s"  IMM
 SG_ M2I_Byrack_SysABStTm_IMM18_03 : 40|16@1+ (0.01,0) [0|655.35] "s"  IMM
 SG_ Reserved_03 : 56|8@1+ (1,0) [0|255] ""  IMM

BO_ 2332111508 M2I_Byrack_SUMDATA18__04: 8 MBMU
 SG_ CRC_M2I_Byrack_IMM18_04 : 0|8@1+ (1,0) [0|255] ""  IMM
 SG_ M2I_Byrack_HVS_IMM18_04 : 8|16@1+ (0.1,0) [0|6553.5] "v"  IMM
 SG_ M2I_Byrack_Enable_IMM18_04 : 24|2@1+ (1,0) [0|3] ""  IMM
 SG_ M2I_Byrack_ReVeEnable_IMM18_04 : 26|2@1+ (1,0) [0|3] ""  IMM
 SG_ Reserved_04 : 28|4@1+ (1,0) [0|15] ""  IMM
 SG_ M2I_Byrack_IsPostTm_IMM18_04 : 32|8@1+ (0.01,0) [0|2.55] "s"  IMM
 SG_ M2I_Byrack_SysABStTm_IMM18_04 : 40|16@1+ (0.01,0) [0|655.35] "s"  IMM
 SG_ Reserved_04 : 56|8@1+ (1,0) [0|255] ""  IMM

BO_ 2332111509 M2I_Byrack_SUMDATA18__05: 8 MBMU
 SG_ CRC_M2I_Byrack_IMM18_05 : 0|8@1+ (1,0) [0|255] ""  IMM
 SG_ M2I_Byrack_HVS_IMM18_05 : 8|16@1+ (0.1,0) [0|6553.5] "v"  IMM
 SG_ M2I_Byrack_Enable_IMM18_05 : 24|2@1+ (1,0) [0|3] ""  IMM
 SG_ M2I_Byrack_ReVeEnable_IMM18_05 : 26|2@1+ (1,0) [0|3] ""  IMM
 SG_ Reserved_05 : 28|4@1+ (1,0) [0|15] ""  IMM
 SG_ M2I_Byrack_IsPostTm_IMM18_05 : 32|8@1+ (0.01,0) [0|2.55] "s"  IMM
 SG_ M2I_Byrack_SysABStTm_IMM18_05 : 40|16@1+ (0.01,0) [0|655.35] "s"  IMM
 SG_ Reserved_05 : 56|8@1+ (1,0) [0|255] ""  IMM

BO_ 2332111510 M2I_Byrack_SUMDATA18__06: 8 MBMU
 SG_ CRC_M2I_Byrack_IMM18_06 : 0|8@1+ (1,0) [0|255] ""  IMM
 SG_ M2I_Byrack_HVS_IMM18_06 : 8|16@1+ (0.1,0) [0|6553.5] "v"  IMM
 SG_ M2I_Byrack_Enable_IMM18_06 : 24|2@1+ (1,0) [0|3] ""  IMM
 SG_ M2I_Byrack_ReVeEnable_IMM18_06 : 26|2@1+ (1,0) [0|3] ""  IMM
 SG_ Reserved_06 : 28|4@1+ (1,0) [0|15] ""  IMM
 SG_ M2I_Byrack_IsPostTm_IMM18_06 : 32|8@1+ (0.01,0) [0|2.55] "s"  IMM
 SG_ M2I_Byrack_SysABStTm_IMM18_06 : 40|16@1+ (0.01,0) [0|655.35] "s"  IMM
 SG_ Reserved_06 : 56|8@1+ (1,0) [0|255] ""  IMM

BO_ 2332111511 M2I_Byrack_SUMDATA18__07: 8 MBMU
 SG_ CRC_M2I_Byrack_IMM18_07 : 0|8@1+ (1,0) [0|255] ""  IMM
 SG_ M2I_Byrack_HVS_IMM18_07 : 8|16@1+ (0.1,0) [0|6553.5] "v"  IMM
 SG_ M2I_Byrack_Enable_IMM18_07 : 24|2@1+ (1,0) [0|3] ""  IMM
 SG_ M2I_Byrack_ReVeEnable_IMM18_07 : 26|2@1+ (1,0) [0|3] ""  IMM
 SG_ Reserved_07 : 28|4@1+ (1,0) [0|15] ""  IMM
 SG_ M2I_Byrack_IsPostTm_IMM18_07 : 32|8@1+ (0.01,0) [0|2.55] "s"  IMM
 SG_ M2I_Byrack_SysABStTm_IMM18_07 : 40|16@1+ (0.01,0) [0|655.35] "s"  IMM
 SG_ Reserved_07 : 56|8@1+ (1,0) [0|255] ""  IMM

BO_ 2332111512 M2I_Byrack_SUMDATA18__08: 8 MBMU
 SG_ CRC_M2I_Byrack_IMM18_08 : 0|8@1+ (1,0) [0|255] ""  IMM
 SG_ M2I_Byrack_HVS_IMM18_08 : 8|16@1+ (0.1,0) [0|6553.5] "v"  IMM
 SG_ M2I_Byrack_Enable_IMM18_08 : 24|2@1+ (1,0) [0|3] ""  IMM
 SG_ M2I_Byrack_ReVeEnable_IMM18_08 : 26|2@1+ (1,0) [0|3] ""  IMM
 SG_ Reserved_08 : 28|4@1+ (1,0) [0|15] ""  IMM
 SG_ M2I_Byrack_IsPostTm_IMM18_08 : 32|8@1+ (0.01,0) [0|2.55] "s"  IMM
 SG_ M2I_Byrack_SysABStTm_IMM18_08 : 40|16@1+ (0.01,0) [0|655.35] "s"  IMM
 SG_ Reserved_08 : 56|8@1+ (1,0) [0|255] ""  IMM

BO_ 2332111513 M2I_Byrack_SUMDATA18__09: 8 MBMU
 SG_ CRC_M2I_Byrack_IMM18_09 : 0|8@1+ (1,0) [0|255] ""  IMM
 SG_ M2I_Byrack_HVS_IMM18_09 : 8|16@1+ (0.1,0) [0|6553.5] "v"  IMM
 SG_ M2I_Byrack_Enable_IMM18_09 : 24|2@1+ (1,0) [0|3] ""  IMM
 SG_ M2I_Byrack_ReVeEnable_IMM18_09 : 26|2@1+ (1,0) [0|3] ""  IMM
 SG_ Reserved_09 : 28|4@1+ (1,0) [0|15] ""  IMM
 SG_ M2I_Byrack_IsPostTm_IMM18_09 : 32|8@1+ (0.01,0) [0|2.55] "s"  IMM
 SG_ M2I_Byrack_SysABStTm_IMM18_09 : 40|16@1+ (0.01,0) [0|655.35] "s"  IMM
 SG_ Reserved_09 : 56|8@1+ (1,0) [0|255] ""  IMM

BO_ 2332111514 M2I_Byrack_SUMDATA18__10: 8 MBMU
 SG_ CRC_M2I_Byrack_IMM18_10 : 0|8@1+ (1,0) [0|255] ""  IMM
 SG_ M2I_Byrack_HVS_IMM18_10 : 8|16@1+ (0.1,0) [0|6553.5] "v"  IMM
 SG_ M2I_Byrack_Enable_IMM18_10 : 24|2@1+ (1,0) [0|3] ""  IMM
 SG_ M2I_Byrack_ReVeEnable_IMM18_10 : 26|2@1+ (1,0) [0|3] ""  IMM
 SG_ Reserved_10 : 28|4@1+ (1,0) [0|15] ""  IMM
 SG_ M2I_Byrack_IsPostTm_IMM18_10 : 32|8@1+ (0.01,0) [0|2.55] "s"  IMM
 SG_ M2I_Byrack_SysABStTm_IMM18_10 : 40|16@1+ (0.01,0) [0|655.35] "s"  IMM
 SG_ Reserved_10 : 56|8@1+ (1,0) [0|255] ""  IMM

BO_ 2332111515 M2I_Byrack_SUMDATA18__11: 8 MBMU
 SG_ CRC_M2I_Byrack_IMM18_11 : 0|8@1+ (1,0) [0|255] ""  IMM
 SG_ M2I_Byrack_HVS_IMM18_11 : 8|16@1+ (0.1,0) [0|6553.5] "v"  IMM
 SG_ M2I_Byrack_Enable_IMM18_11 : 24|2@1+ (1,0) [0|3] ""  IMM
 SG_ M2I_Byrack_ReVeEnable_IMM18_11 : 26|2@1+ (1,0) [0|3] ""  IMM
 SG_ Reserved_11 : 28|4@1+ (1,0) [0|15] ""  IMM
 SG_ M2I_Byrack_IsPostTm_IMM18_11 : 32|8@1+ (0.01,0) [0|2.55] "s"  IMM
 SG_ M2I_Byrack_SysABStTm_IMM18_11 : 40|16@1+ (0.01,0) [0|655.35] "s"  IMM
 SG_ Reserved_11 : 56|8@1+ (1,0) [0|255] ""  IMM

BO_ 2332111516 M2I_Byrack_SUMDATA18__12: 8 MBMU
 SG_ CRC_M2I_Byrack_IMM18_12 : 0|8@1+ (1,0) [0|255] ""  IMM
 SG_ M2I_Byrack_HVS_IMM18_12 : 8|16@1+ (0.1,0) [0|6553.5] "v"  IMM
 SG_ M2I_Byrack_Enable_IMM18_12 : 24|2@1+ (1,0) [0|3] ""  IMM
 SG_ M2I_Byrack_ReVeEnable_IMM18_12 : 26|2@1+ (1,0) [0|3] ""  IMM
 SG_ Reserved_12 : 28|4@1+ (1,0) [0|15] ""  IMM
 SG_ M2I_Byrack_IsPostTm_IMM18_12 : 32|8@1+ (0.01,0) [0|2.55] "s"  IMM
 SG_ M2I_Byrack_SysABStTm_IMM18_12 : 40|16@1+ (0.01,0) [0|655.35] "s"  IMM
 SG_ Reserved_12 : 56|8@1+ (1,0) [0|255] ""  IMM

BO_ 2332111517 M2I_Byrack_SUMDATA18__13: 8 MBMU
 SG_ CRC_M2I_Byrack_IMM18_13 : 0|8@1+ (1,0) [0|255] ""  IMM
 SG_ M2I_Byrack_HVS_IMM18_13 : 8|16@1+ (0.1,0) [0|6553.5] "v"  IMM
 SG_ M2I_Byrack_Enable_IMM18_13 : 24|2@1+ (1,0) [0|3] ""  IMM
 SG_ M2I_Byrack_ReVeEnable_IMM18_13 : 26|2@1+ (1,0) [0|3] ""  IMM
 SG_ Reserved_13 : 28|4@1+ (1,0) [0|15] ""  IMM
 SG_ M2I_Byrack_IsPostTm_IMM18_13 : 32|8@1+ (0.01,0) [0|2.55] "s"  IMM
 SG_ M2I_Byrack_SysABStTm_IMM18_13 : 40|16@1+ (0.01,0) [0|655.35] "s"  IMM
 SG_ Reserved_13 : 56|8@1+ (1,0) [0|255] ""  IMM

BO_ 2332111518 M2I_Byrack_SUMDATA18__14: 8 MBMU
 SG_ CRC_M2I_Byrack_IMM18_14 : 0|8@1+ (1,0) [0|255] ""  IMM
 SG_ M2I_Byrack_HVS_IMM18_14 : 8|16@1+ (0.1,0) [0|6553.5] "v"  IMM
 SG_ M2I_Byrack_Enable_IMM18_14 : 24|2@1+ (1,0) [0|3] ""  IMM
 SG_ M2I_Byrack_ReVeEnable_IMM18_14 : 26|2@1+ (1,0) [0|3] ""  IMM
 SG_ Reserved_14 : 28|4@1+ (1,0) [0|15] ""  IMM
 SG_ M2I_Byrack_IsPostTm_IMM18_14 : 32|8@1+ (0.01,0) [0|2.55] "s"  IMM
 SG_ M2I_Byrack_SysABStTm_IMM18_14 : 40|16@1+ (0.01,0) [0|655.35] "s"  IMM
 SG_ Reserved_14 : 56|8@1+ (1,0) [0|255] ""  IMM

BO_ 2332111519 M2I_Byrack_SUMDATA18__15: 8 MBMU
 SG_ CRC_M2I_Byrack_IMM18_15 : 0|8@1+ (1,0) [0|255] ""  IMM
 SG_ M2I_Byrack_HVS_IMM18_15 : 8|16@1+ (0.1,0) [0|6553.5] "v"  IMM
 SG_ M2I_Byrack_Enable_IMM18_15 : 24|2@1+ (1,0) [0|3] ""  IMM
 SG_ M2I_Byrack_ReVeEnable_IMM18_15 : 26|2@1+ (1,0) [0|3] ""  IMM
 SG_ Reserved_15 : 28|4@1+ (1,0) [0|15] ""  IMM
 SG_ M2I_Byrack_IsPostTm_IMM18_15 : 32|8@1+ (0.01,0) [0|2.55] "s"  IMM
 SG_ M2I_Byrack_SysABStTm_IMM18_15 : 40|16@1+ (0.01,0) [0|655.35] "s"  IMM
 SG_ Reserved_15 : 56|8@1+ (1,0) [0|255] ""  IMM

BO_ 2332111520 M2I_Byrack_SUMDATA18__16: 8 MBMU
 SG_ CRC_M2I_Byrack_IMM18_16 : 0|8@1+ (1,0) [0|255] ""  IMM
 SG_ M2I_Byrack_HVS_IMM18_16 : 8|16@1+ (0.1,0) [0|6553.5] "v"  IMM
 SG_ M2I_Byrack_Enable_IMM18_16 : 24|2@1+ (1,0) [0|3] ""  IMM
 SG_ M2I_Byrack_ReVeEnable_IMM18_16 : 26|2@1+ (1,0) [0|3] ""  IMM
 SG_ Reserved_16 : 28|4@1+ (1,0) [0|15] ""  IMM
 SG_ M2I_Byrack_IsPostTm_IMM18_16 : 32|8@1+ (0.01,0) [0|2.55] "s"  IMM
 SG_ M2I_Byrack_SysABStTm_IMM18_16 : 40|16@1+ (0.01,0) [0|655.35] "s"  IMM
 SG_ Reserved_16 : 56|8@1+ (1,0) [0|255] ""  IMM

BO_ 2332111521 M2I_Byrack_SUMDATA18__17: 8 MBMU
 SG_ CRC_M2I_Byrack_IMM18_17 : 0|8@1+ (1,0) [0|255] ""  IMM
 SG_ M2I_Byrack_HVS_IMM18_17 : 8|16@1+ (0.1,0) [0|6553.5] "v"  IMM
 SG_ M2I_Byrack_Enable_IMM18_17 : 24|2@1+ (1,0) [0|3] ""  IMM
 SG_ M2I_Byrack_ReVeEnable_IMM18_17 : 26|2@1+ (1,0) [0|3] ""  IMM
 SG_ Reserved_17 : 28|4@1+ (1,0) [0|15] ""  IMM
 SG_ M2I_Byrack_IsPostTm_IMM18_17 : 32|8@1+ (0.01,0) [0|2.55] "s"  IMM
 SG_ M2I_Byrack_SysABStTm_IMM18_17 : 40|16@1+ (0.01,0) [0|655.35] "s"  IMM
 SG_ Reserved_17 : 56|8@1+ (1,0) [0|255] ""  IMM

BO_ 2332111522 M2I_Byrack_SUMDATA18__18: 8 MBMU
 SG_ CRC_M2I_Byrack_IMM18_18 : 0|8@1+ (1,0) [0|255] ""  IMM
 SG_ M2I_Byrack_HVS_IMM18_18 : 8|16@1+ (0.1,0) [0|6553.5] "v"  IMM
 SG_ M2I_Byrack_Enable_IMM18_18 : 24|2@1+ (1,0) [0|3] ""  IMM
 SG_ M2I_Byrack_ReVeEnable_IMM18_18 : 26|2@1+ (1,0) [0|3] ""  IMM
 SG_ Reserved_18 : 28|4@1+ (1,0) [0|15] ""  IMM
 SG_ M2I_Byrack_IsPostTm_IMM18_18 : 32|8@1+ (0.01,0) [0|2.55] "s"  IMM
 SG_ M2I_Byrack_SysABStTm_IMM18_18 : 40|16@1+ (0.01,0) [0|655.35] "s"  IMM
 SG_ Reserved_18 : 56|8@1+ (1,0) [0|255] ""  IMM

BO_ 2332111523 M2I_Byrack_SUMDATA18__19: 8 MBMU
 SG_ CRC_M2I_Byrack_IMM18_19 : 0|8@1+ (1,0) [0|255] ""  IMM
 SG_ M2I_Byrack_HVS_IMM18_19 : 8|16@1+ (0.1,0) [0|6553.5] "v"  IMM
 SG_ M2I_Byrack_Enable_IMM18_19 : 24|2@1+ (1,0) [0|3] ""  IMM
 SG_ M2I_Byrack_ReVeEnable_IMM18_19 : 26|2@1+ (1,0) [0|3] ""  IMM
 SG_ Reserved_19 : 28|4@1+ (1,0) [0|15] ""  IMM
 SG_ M2I_Byrack_IsPostTm_IMM18_19 : 32|8@1+ (0.01,0) [0|2.55] "s"  IMM
 SG_ M2I_Byrack_SysABStTm_IMM18_19 : 40|16@1+ (0.01,0) [0|655.35] "s"  IMM
 SG_ Reserved_19 : 56|8@1+ (1,0) [0|255] ""  IMM

BO_ 2332111524 M2I_Byrack_SUMDATA18__20: 8 MBMU
 SG_ CRC_M2I_Byrack_IMM18_20 : 0|8@1+ (1,0) [0|255] ""  IMM
 SG_ M2I_Byrack_HVS_IMM18_20 : 8|16@1+ (0.1,0) [0|6553.5] "v"  IMM
 SG_ M2I_Byrack_Enable_IMM18_20 : 24|2@1+ (1,0) [0|3] ""  IMM
 SG_ M2I_Byrack_ReVeEnable_IMM18_20 : 26|2@1+ (1,0) [0|3] ""  IMM
 SG_ Reserved_20 : 28|4@1+ (1,0) [0|15] ""  IMM
 SG_ M2I_Byrack_IsPostTm_IMM18_20 : 32|8@1+ (0.01,0) [0|2.55] "s"  IMM
 SG_ M2I_Byrack_SysABStTm_IMM18_20 : 40|16@1+ (0.01,0) [0|655.35] "s"  IMM
 SG_ Reserved_20 : 56|8@1+ (1,0) [0|255] ""  IMM

BO_ 2332111525 M2I_Byrack_SUMDATA18__21: 8 MBMU
 SG_ CRC_M2I_Byrack_IMM18_21 : 0|8@1+ (1,0) [0|255] ""  IMM
 SG_ M2I_Byrack_HVS_IMM18_21 : 8|16@1+ (0.1,0) [0|6553.5] "v"  IMM
 SG_ M2I_Byrack_Enable_IMM18_21 : 24|2@1+ (1,0) [0|3] ""  IMM
 SG_ M2I_Byrack_ReVeEnable_IMM18_21 : 26|2@1+ (1,0) [0|3] ""  IMM
 SG_ Reserved_21 : 28|4@1+ (1,0) [0|15] ""  IMM
 SG_ M2I_Byrack_IsPostTm_IMM18_21 : 32|8@1+ (0.01,0) [0|2.55] "s"  IMM
 SG_ M2I_Byrack_SysABStTm_IMM18_21 : 40|16@1+ (0.01,0) [0|655.35] "s"  IMM
 SG_ Reserved_21 : 56|8@1+ (1,0) [0|255] ""  IMM

BO_ 2332111526 M2I_Byrack_SUMDATA18__22: 8 MBMU
 SG_ CRC_M2I_Byrack_IMM18_22 : 0|8@1+ (1,0) [0|255] ""  IMM
 SG_ M2I_Byrack_HVS_IMM18_22 : 8|16@1+ (0.1,0) [0|6553.5] "v"  IMM
 SG_ M2I_Byrack_Enable_IMM18_22 : 24|2@1+ (1,0) [0|3] ""  IMM
 SG_ M2I_Byrack_ReVeEnable_IMM18_22 : 26|2@1+ (1,0) [0|3] ""  IMM
 SG_ Reserved_22 : 28|4@1+ (1,0) [0|15] ""  IMM
 SG_ M2I_Byrack_IsPostTm_IMM18_22 : 32|8@1+ (0.01,0) [0|2.55] "s"  IMM
 SG_ M2I_Byrack_SysABStTm_IMM18_22 : 40|16@1+ (0.01,0) [0|655.35] "s"  IMM
 SG_ Reserved_22 : 56|8@1+ (1,0) [0|255] ""  IMM

BO_ 2332111527 M2I_Byrack_SUMDATA18__23: 8 MBMU
 SG_ CRC_M2I_Byrack_IMM18_23 : 0|8@1+ (1,0) [0|255] ""  IMM
 SG_ M2I_Byrack_HVS_IMM18_23 : 8|16@1+ (0.1,0) [0|6553.5] "v"  IMM
 SG_ M2I_Byrack_Enable_IMM18_23 : 24|2@1+ (1,0) [0|3] ""  IMM
 SG_ M2I_Byrack_ReVeEnable_IMM18_23 : 26|2@1+ (1,0) [0|3] ""  IMM
 SG_ Reserved_23 : 28|4@1+ (1,0) [0|15] ""  IMM
 SG_ M2I_Byrack_IsPostTm_IMM18_23 : 32|8@1+ (0.01,0) [0|2.55] "s"  IMM
 SG_ M2I_Byrack_SysABStTm_IMM18_23 : 40|16@1+ (0.01,0) [0|655.35] "s"  IMM
 SG_ Reserved_23 : 56|8@1+ (1,0) [0|255] ""  IMM

BO_ 2332111528 M2I_Byrack_SUMDATA18__24: 8 MBMU
 SG_ CRC_M2I_Byrack_IMM18_24 : 0|8@1+ (1,0) [0|255] ""  IMM
 SG_ M2I_Byrack_HVS_IMM18_24 : 8|16@1+ (0.1,0) [0|6553.5] "v"  IMM
 SG_ M2I_Byrack_Enable_IMM18_24 : 24|2@1+ (1,0) [0|3] ""  IMM
 SG_ M2I_Byrack_ReVeEnable_IMM18_24 : 26|2@1+ (1,0) [0|3] ""  IMM
 SG_ Reserved_24 : 28|4@1+ (1,0) [0|15] ""  IMM
 SG_ M2I_Byrack_IsPostTm_IMM18_24 : 32|8@1+ (0.01,0) [0|2.55] "s"  IMM
 SG_ M2I_Byrack_SysABStTm_IMM18_24 : 40|16@1+ (0.01,0) [0|655.35] "s"  IMM
 SG_ Reserved_24 : 56|8@1+ (1,0) [0|255] ""  IMM

BO_ 2332111529 M2I_Byrack_SUMDATA18__25: 8 MBMU
 SG_ CRC_M2I_Byrack_IMM18_25 : 0|8@1+ (1,0) [0|255] ""  IMM
 SG_ M2I_Byrack_HVS_IMM18_25 : 8|16@1+ (0.1,0) [0|6553.5] "v"  IMM
 SG_ M2I_Byrack_Enable_IMM18_25 : 24|2@1+ (1,0) [0|3] ""  IMM
 SG_ M2I_Byrack_ReVeEnable_IMM18_25 : 26|2@1+ (1,0) [0|3] ""  IMM
 SG_ Reserved_25 : 28|4@1+ (1,0) [0|15] ""  IMM
 SG_ M2I_Byrack_IsPostTm_IMM18_25 : 32|8@1+ (0.01,0) [0|2.55] "s"  IMM
 SG_ M2I_Byrack_SysABStTm_IMM18_25 : 40|16@1+ (0.01,0) [0|655.35] "s"  IMM
 SG_ Reserved_25 : 56|8@1+ (1,0) [0|255] ""  IMM

BO_ 2332111530 M2I_Byrack_SUMDATA18__26: 8 MBMU
 SG_ CRC_M2I_Byrack_IMM18_26 : 0|8@1+ (1,0) [0|255] ""  IMM
 SG_ M2I_Byrack_HVS_IMM18_26 : 8|16@1+ (0.1,0) [0|6553.5] "v"  IMM
 SG_ M2I_Byrack_Enable_IMM18_26 : 24|2@1+ (1,0) [0|3] ""  IMM
 SG_ M2I_Byrack_ReVeEnable_IMM18_26 : 26|2@1+ (1,0) [0|3] ""  IMM
 SG_ Reserved_26 : 28|4@1+ (1,0) [0|15] ""  IMM
 SG_ M2I_Byrack_IsPostTm_IMM18_26 : 32|8@1+ (0.01,0) [0|2.55] "s"  IMM
 SG_ M2I_Byrack_SysABStTm_IMM18_26 : 40|16@1+ (0.01,0) [0|655.35] "s"  IMM
 SG_ Reserved_26 : 56|8@1+ (1,0) [0|255] ""  IMM

BO_ 2332111531 M2I_Byrack_SUMDATA18__27: 8 MBMU
 SG_ CRC_M2I_Byrack_IMM18_27 : 0|8@1+ (1,0) [0|255] ""  IMM
 SG_ M2I_Byrack_HVS_IMM18_27 : 8|16@1+ (0.1,0) [0|6553.5] "v"  IMM
 SG_ M2I_Byrack_Enable_IMM18_27 : 24|2@1+ (1,0) [0|3] ""  IMM
 SG_ M2I_Byrack_ReVeEnable_IMM18_27 : 26|2@1+ (1,0) [0|3] ""  IMM
 SG_ Reserved_27 : 28|4@1+ (1,0) [0|15] ""  IMM
 SG_ M2I_Byrack_IsPostTm_IMM18_27 : 32|8@1+ (0.01,0) [0|2.55] "s"  IMM
 SG_ M2I_Byrack_SysABStTm_IMM18_27 : 40|16@1+ (0.01,0) [0|655.35] "s"  IMM
 SG_ Reserved_27 : 56|8@1+ (1,0) [0|255] ""  IMM

BO_ 2332111532 M2I_Byrack_SUMDATA18__28: 8 MBMU
 SG_ CRC_M2I_Byrack_IMM18_28 : 0|8@1+ (1,0) [0|255] ""  IMM
 SG_ M2I_Byrack_HVS_IMM18_28 : 8|16@1+ (0.1,0) [0|6553.5] "v"  IMM
 SG_ M2I_Byrack_Enable_IMM18_28 : 24|2@1+ (1,0) [0|3] ""  IMM
 SG_ M2I_Byrack_ReVeEnable_IMM18_28 : 26|2@1+ (1,0) [0|3] ""  IMM
 SG_ Reserved_28 : 28|4@1+ (1,0) [0|15] ""  IMM
 SG_ M2I_Byrack_IsPostTm_IMM18_28 : 32|8@1+ (0.01,0) [0|2.55] "s"  IMM
 SG_ M2I_Byrack_SysABStTm_IMM18_28 : 40|16@1+ (0.01,0) [0|655.35] "s"  IMM
 SG_ Reserved_28 : 56|8@1+ (1,0) [0|255] ""  IMM

BO_ 2332111533 M2I_Byrack_SUMDATA18__29: 8 MBMU
 SG_ CRC_M2I_Byrack_IMM18_29 : 0|8@1+ (1,0) [0|255] ""  IMM
 SG_ M2I_Byrack_HVS_IMM18_29 : 8|16@1+ (0.1,0) [0|6553.5] "v"  IMM
 SG_ M2I_Byrack_Enable_IMM18_29 : 24|2@1+ (1,0) [0|3] ""  IMM
 SG_ M2I_Byrack_ReVeEnable_IMM18_29 : 26|2@1+ (1,0) [0|3] ""  IMM
 SG_ Reserved_29 : 28|4@1+ (1,0) [0|15] ""  IMM
 SG_ M2I_Byrack_IsPostTm_IMM18_29 : 32|8@1+ (0.01,0) [0|2.55] "s"  IMM
 SG_ M2I_Byrack_SysABStTm_IMM18_29 : 40|16@1+ (0.01,0) [0|655.35] "s"  IMM
 SG_ Reserved_29 : 56|8@1+ (1,0) [0|255] ""  IMM

BO_ 2332111534 M2I_Byrack_SUMDATA18__30: 8 MBMU
 SG_ CRC_M2I_Byrack_IMM18_30 : 0|8@1+ (1,0) [0|255] ""  IMM
 SG_ M2I_Byrack_HVS_IMM18_30 : 8|16@1+ (0.1,0) [0|6553.5] "v"  IMM
 SG_ M2I_Byrack_Enable_IMM18_30 : 24|2@1+ (1,0) [0|3] ""  IMM
 SG_ M2I_Byrack_ReVeEnable_IMM18_30 : 26|2@1+ (1,0) [0|3] ""  IMM
 SG_ Reserved_30 : 28|4@1+ (1,0) [0|15] ""  IMM
 SG_ M2I_Byrack_IsPostTm_IMM18_30 : 32|8@1+ (0.01,0) [0|2.55] "s"  IMM
 SG_ M2I_Byrack_SysABStTm_IMM18_30 : 40|16@1+ (0.01,0) [0|655.35] "s"  IMM
 SG_ Reserved_30 : 56|8@1+ (1,0) [0|255] ""  IMM

BO_ 2332111535 M2I_Byrack_SUMDATA18__31: 8 MBMU
 SG_ CRC_M2I_Byrack_IMM18_31 : 0|8@1+ (1,0) [0|255] ""  IMM
 SG_ M2I_Byrack_HVS_IMM18_31 : 8|16@1+ (0.1,0) [0|6553.5] "v"  IMM
 SG_ M2I_Byrack_Enable_IMM18_31 : 24|2@1+ (1,0) [0|3] ""  IMM
 SG_ M2I_Byrack_ReVeEnable_IMM18_31 : 26|2@1+ (1,0) [0|3] ""  IMM
 SG_ Reserved_31 : 28|4@1+ (1,0) [0|15] ""  IMM
 SG_ M2I_Byrack_IsPostTm_IMM18_31 : 32|8@1+ (0.01,0) [0|2.55] "s"  IMM
 SG_ M2I_Byrack_SysABStTm_IMM18_31 : 40|16@1+ (0.01,0) [0|655.35] "s"  IMM
 SG_ Reserved_31 : 56|8@1+ (1,0) [0|255] ""  IMM

BO_ 2332111761 M2I_Byrack_SUMDATA19__01: 8 MBMU
 SG_ CRC_M2I_Byrack_IMM19_01 : 0|8@1+ (1,0) [0|255] ""  IMM
 SG_ M2I_Byrack_HVS_IMM19_01 : 8|16@1+ (0.1,0) [0|6553.5] "v"  IMM
 SG_ M2I_Byrack_Enable_IMM9_01 : 24|2@1+ (1,0) [0|3] ""  IMM
 SG_ M2I_Byrack_ReVeEnable_IMM19_01 : 26|2@1+ (1,0) [0|3] ""  IMM
 SG_ Reserved_01 : 28|4@1+ (1,0) [0|15] ""  IMM
 SG_ M2I_Byrack_IsPostTm_IMM19_01 : 32|8@1+ (0.01,0) [0|2.55] "s"  IMM
 SG_ M2I_Byrack_SysABStTm_IMM19_01 : 40|16@1+ (0.01,0) [0|655.35] "s"  IMM
 SG_ Reserved_01 : 56|8@1+ (1,0) [0|255] ""  IMM

BO_ 2332111762 M2I_Byrack_SUMDATA19__02: 8 MBMU
 SG_ CRC_M2I_Byrack_IMM19_02 : 0|8@1+ (1,0) [0|255] ""  IMM
 SG_ M2I_Byrack_HVS_IMM19_02 : 8|16@1+ (0.1,0) [0|6553.5] "v"  IMM
 SG_ M2I_Byrack_Enable_IMM9_02 : 24|2@1+ (1,0) [0|3] ""  IMM
 SG_ M2I_Byrack_ReVeEnable_IMM19_02 : 26|2@1+ (1,0) [0|3] ""  IMM
 SG_ Reserved_02 : 28|4@1+ (1,0) [0|15] ""  IMM
 SG_ M2I_Byrack_IsPostTm_IMM19_02 : 32|8@1+ (0.01,0) [0|2.55] "s"  IMM
 SG_ M2I_Byrack_SysABStTm_IMM19_02 : 40|16@1+ (0.01,0) [0|655.35] "s"  IMM
 SG_ Reserved_02 : 56|8@1+ (1,0) [0|255] ""  IMM

BO_ 2332111763 M2I_Byrack_SUMDATA19__03: 8 MBMU
 SG_ CRC_M2I_Byrack_IMM19_03 : 0|8@1+ (1,0) [0|255] ""  IMM
 SG_ M2I_Byrack_HVS_IMM19_03 : 8|16@1+ (0.1,0) [0|6553.5] "v"  IMM
 SG_ M2I_Byrack_Enable_IMM9_03 : 24|2@1+ (1,0) [0|3] ""  IMM
 SG_ M2I_Byrack_ReVeEnable_IMM19_03 : 26|2@1+ (1,0) [0|3] ""  IMM
 SG_ Reserved_03 : 28|4@1+ (1,0) [0|15] ""  IMM
 SG_ M2I_Byrack_IsPostTm_IMM19_03 : 32|8@1+ (0.01,0) [0|2.55] "s"  IMM
 SG_ M2I_Byrack_SysABStTm_IMM19_03 : 40|16@1+ (0.01,0) [0|655.35] "s"  IMM
 SG_ Reserved_03 : 56|8@1+ (1,0) [0|255] ""  IMM

BO_ 2332111764 M2I_Byrack_SUMDATA19__04: 8 MBMU
 SG_ CRC_M2I_Byrack_IMM19_04 : 0|8@1+ (1,0) [0|255] ""  IMM
 SG_ M2I_Byrack_HVS_IMM19_04 : 8|16@1+ (0.1,0) [0|6553.5] "v"  IMM
 SG_ M2I_Byrack_Enable_IMM9_04 : 24|2@1+ (1,0) [0|3] ""  IMM
 SG_ M2I_Byrack_ReVeEnable_IMM19_04 : 26|2@1+ (1,0) [0|3] ""  IMM
 SG_ Reserved_04 : 28|4@1+ (1,0) [0|15] ""  IMM
 SG_ M2I_Byrack_IsPostTm_IMM19_04 : 32|8@1+ (0.01,0) [0|2.55] "s"  IMM
 SG_ M2I_Byrack_SysABStTm_IMM19_04 : 40|16@1+ (0.01,0) [0|655.35] "s"  IMM
 SG_ Reserved_04 : 56|8@1+ (1,0) [0|255] ""  IMM

BO_ 2332111765 M2I_Byrack_SUMDATA19__05: 8 MBMU
 SG_ CRC_M2I_Byrack_IMM19_05 : 0|8@1+ (1,0) [0|255] ""  IMM
 SG_ M2I_Byrack_HVS_IMM19_05 : 8|16@1+ (0.1,0) [0|6553.5] "v"  IMM
 SG_ M2I_Byrack_Enable_IMM9_05 : 24|2@1+ (1,0) [0|3] ""  IMM
 SG_ M2I_Byrack_ReVeEnable_IMM19_05 : 26|2@1+ (1,0) [0|3] ""  IMM
 SG_ Reserved_05 : 28|4@1+ (1,0) [0|15] ""  IMM
 SG_ M2I_Byrack_IsPostTm_IMM19_05 : 32|8@1+ (0.01,0) [0|2.55] "s"  IMM
 SG_ M2I_Byrack_SysABStTm_IMM19_05 : 40|16@1+ (0.01,0) [0|655.35] "s"  IMM
 SG_ Reserved_05 : 56|8@1+ (1,0) [0|255] ""  IMM

BO_ 2332111766 M2I_Byrack_SUMDATA19__06: 8 MBMU
 SG_ CRC_M2I_Byrack_IMM19_06 : 0|8@1+ (1,0) [0|255] ""  IMM
 SG_ M2I_Byrack_HVS_IMM19_06 : 8|16@1+ (0.1,0) [0|6553.5] "v"  IMM
 SG_ M2I_Byrack_Enable_IMM9_06 : 24|2@1+ (1,0) [0|3] ""  IMM
 SG_ M2I_Byrack_ReVeEnable_IMM19_06 : 26|2@1+ (1,0) [0|3] ""  IMM
 SG_ Reserved_06 : 28|4@1+ (1,0) [0|15] ""  IMM
 SG_ M2I_Byrack_IsPostTm_IMM19_06 : 32|8@1+ (0.01,0) [0|2.55] "s"  IMM
 SG_ M2I_Byrack_SysABStTm_IMM19_06 : 40|16@1+ (0.01,0) [0|655.35] "s"  IMM
 SG_ Reserved_06 : 56|8@1+ (1,0) [0|255] ""  IMM

BO_ 2332111767 M2I_Byrack_SUMDATA19__07: 8 MBMU
 SG_ CRC_M2I_Byrack_IMM19_07 : 0|8@1+ (1,0) [0|255] ""  IMM
 SG_ M2I_Byrack_HVS_IMM19_07 : 8|16@1+ (0.1,0) [0|6553.5] "v"  IMM
 SG_ M2I_Byrack_Enable_IMM9_07 : 24|2@1+ (1,0) [0|3] ""  IMM
 SG_ M2I_Byrack_ReVeEnable_IMM19_07 : 26|2@1+ (1,0) [0|3] ""  IMM
 SG_ Reserved_07 : 28|4@1+ (1,0) [0|15] ""  IMM
 SG_ M2I_Byrack_IsPostTm_IMM19_07 : 32|8@1+ (0.01,0) [0|2.55] "s"  IMM
 SG_ M2I_Byrack_SysABStTm_IMM19_07 : 40|16@1+ (0.01,0) [0|655.35] "s"  IMM
 SG_ Reserved_07 : 56|8@1+ (1,0) [0|255] ""  IMM

BO_ 2332111768 M2I_Byrack_SUMDATA19__08: 8 MBMU
 SG_ CRC_M2I_Byrack_IMM19_08 : 0|8@1+ (1,0) [0|255] ""  IMM
 SG_ M2I_Byrack_HVS_IMM19_08 : 8|16@1+ (0.1,0) [0|6553.5] "v"  IMM
 SG_ M2I_Byrack_Enable_IMM9_08 : 24|2@1+ (1,0) [0|3] ""  IMM
 SG_ M2I_Byrack_ReVeEnable_IMM19_08 : 26|2@1+ (1,0) [0|3] ""  IMM
 SG_ Reserved_08 : 28|4@1+ (1,0) [0|15] ""  IMM
 SG_ M2I_Byrack_IsPostTm_IMM19_08 : 32|8@1+ (0.01,0) [0|2.55] "s"  IMM
 SG_ M2I_Byrack_SysABStTm_IMM19_08 : 40|16@1+ (0.01,0) [0|655.35] "s"  IMM
 SG_ Reserved_08 : 56|8@1+ (1,0) [0|255] ""  IMM

BO_ 2332111769 M2I_Byrack_SUMDATA19__09: 8 MBMU
 SG_ CRC_M2I_Byrack_IMM19_09 : 0|8@1+ (1,0) [0|255] ""  IMM
 SG_ M2I_Byrack_HVS_IMM19_09 : 8|16@1+ (0.1,0) [0|6553.5] "v"  IMM
 SG_ M2I_Byrack_Enable_IMM9_09 : 24|2@1+ (1,0) [0|3] ""  IMM
 SG_ M2I_Byrack_ReVeEnable_IMM19_09 : 26|2@1+ (1,0) [0|3] ""  IMM
 SG_ Reserved_09 : 28|4@1+ (1,0) [0|15] ""  IMM
 SG_ M2I_Byrack_IsPostTm_IMM19_09 : 32|8@1+ (0.01,0) [0|2.55] "s"  IMM
 SG_ M2I_Byrack_SysABStTm_IMM19_09 : 40|16@1+ (0.01,0) [0|655.35] "s"  IMM
 SG_ Reserved_09 : 56|8@1+ (1,0) [0|255] ""  IMM

BO_ 2332111770 M2I_Byrack_SUMDATA19__10: 8 MBMU
 SG_ CRC_M2I_Byrack_IMM19_10 : 0|8@1+ (1,0) [0|255] ""  IMM
 SG_ M2I_Byrack_HVS_IMM19_10 : 8|16@1+ (0.1,0) [0|6553.5] "v"  IMM
 SG_ M2I_Byrack_Enable_IMM9_10 : 24|2@1+ (1,0) [0|3] ""  IMM
 SG_ M2I_Byrack_ReVeEnable_IMM19_10 : 26|2@1+ (1,0) [0|3] ""  IMM
 SG_ Reserved_10 : 28|4@1+ (1,0) [0|15] ""  IMM
 SG_ M2I_Byrack_IsPostTm_IMM19_10 : 32|8@1+ (0.01,0) [0|2.55] "s"  IMM
 SG_ M2I_Byrack_SysABStTm_IMM19_10 : 40|16@1+ (0.01,0) [0|655.35] "s"  IMM
 SG_ Reserved_10 : 56|8@1+ (1,0) [0|255] ""  IMM

BO_ 2332111771 M2I_Byrack_SUMDATA19__11: 8 MBMU
 SG_ CRC_M2I_Byrack_IMM19_11 : 0|8@1+ (1,0) [0|255] ""  IMM
 SG_ M2I_Byrack_HVS_IMM19_11 : 8|16@1+ (0.1,0) [0|6553.5] "v"  IMM
 SG_ M2I_Byrack_Enable_IMM9_11 : 24|2@1+ (1,0) [0|3] ""  IMM
 SG_ M2I_Byrack_ReVeEnable_IMM19_11 : 26|2@1+ (1,0) [0|3] ""  IMM
 SG_ Reserved_11 : 28|4@1+ (1,0) [0|15] ""  IMM
 SG_ M2I_Byrack_IsPostTm_IMM19_11 : 32|8@1+ (0.01,0) [0|2.55] "s"  IMM
 SG_ M2I_Byrack_SysABStTm_IMM19_11 : 40|16@1+ (0.01,0) [0|655.35] "s"  IMM
 SG_ Reserved_11 : 56|8@1+ (1,0) [0|255] ""  IMM

BO_ 2332111772 M2I_Byrack_SUMDATA19__12: 8 MBMU
 SG_ CRC_M2I_Byrack_IMM19_12 : 0|8@1+ (1,0) [0|255] ""  IMM
 SG_ M2I_Byrack_HVS_IMM19_12 : 8|16@1+ (0.1,0) [0|6553.5] "v"  IMM
 SG_ M2I_Byrack_Enable_IMM9_12 : 24|2@1+ (1,0) [0|3] ""  IMM
 SG_ M2I_Byrack_ReVeEnable_IMM19_12 : 26|2@1+ (1,0) [0|3] ""  IMM
 SG_ Reserved_12 : 28|4@1+ (1,0) [0|15] ""  IMM
 SG_ M2I_Byrack_IsPostTm_IMM19_12 : 32|8@1+ (0.01,0) [0|2.55] "s"  IMM
 SG_ M2I_Byrack_SysABStTm_IMM19_12 : 40|16@1+ (0.01,0) [0|655.35] "s"  IMM
 SG_ Reserved_12 : 56|8@1+ (1,0) [0|255] ""  IMM

BO_ 2332111773 M2I_Byrack_SUMDATA19__13: 8 MBMU
 SG_ CRC_M2I_Byrack_IMM19_13 : 0|8@1+ (1,0) [0|255] ""  IMM
 SG_ M2I_Byrack_HVS_IMM19_13 : 8|16@1+ (0.1,0) [0|6553.5] "v"  IMM
 SG_ M2I_Byrack_Enable_IMM9_13 : 24|2@1+ (1,0) [0|3] ""  IMM
 SG_ M2I_Byrack_ReVeEnable_IMM19_13 : 26|2@1+ (1,0) [0|3] ""  IMM
 SG_ Reserved_13 : 28|4@1+ (1,0) [0|15] ""  IMM
 SG_ M2I_Byrack_IsPostTm_IMM19_13 : 32|8@1+ (0.01,0) [0|2.55] "s"  IMM
 SG_ M2I_Byrack_SysABStTm_IMM19_13 : 40|16@1+ (0.01,0) [0|655.35] "s"  IMM
 SG_ Reserved_13 : 56|8@1+ (1,0) [0|255] ""  IMM

BO_ 2332111774 M2I_Byrack_SUMDATA19__14: 8 MBMU
 SG_ CRC_M2I_Byrack_IMM19_14 : 0|8@1+ (1,0) [0|255] ""  IMM
 SG_ M2I_Byrack_HVS_IMM19_14 : 8|16@1+ (0.1,0) [0|6553.5] "v"  IMM
 SG_ M2I_Byrack_Enable_IMM9_14 : 24|2@1+ (1,0) [0|3] ""  IMM
 SG_ M2I_Byrack_ReVeEnable_IMM19_14 : 26|2@1+ (1,0) [0|3] ""  IMM
 SG_ Reserved_14 : 28|4@1+ (1,0) [0|15] ""  IMM
 SG_ M2I_Byrack_IsPostTm_IMM19_14 : 32|8@1+ (0.01,0) [0|2.55] "s"  IMM
 SG_ M2I_Byrack_SysABStTm_IMM19_14 : 40|16@1+ (0.01,0) [0|655.35] "s"  IMM
 SG_ Reserved_14 : 56|8@1+ (1,0) [0|255] ""  IMM

BO_ 2332111775 M2I_Byrack_SUMDATA19__15: 8 MBMU
 SG_ CRC_M2I_Byrack_IMM19_15 : 0|8@1+ (1,0) [0|255] ""  IMM
 SG_ M2I_Byrack_HVS_IMM19_15 : 8|16@1+ (0.1,0) [0|6553.5] "v"  IMM
 SG_ M2I_Byrack_Enable_IMM9_15 : 24|2@1+ (1,0) [0|3] ""  IMM
 SG_ M2I_Byrack_ReVeEnable_IMM19_15 : 26|2@1+ (1,0) [0|3] ""  IMM
 SG_ Reserved_15 : 28|4@1+ (1,0) [0|15] ""  IMM
 SG_ M2I_Byrack_IsPostTm_IMM19_15 : 32|8@1+ (0.01,0) [0|2.55] "s"  IMM
 SG_ M2I_Byrack_SysABStTm_IMM19_15 : 40|16@1+ (0.01,0) [0|655.35] "s"  IMM
 SG_ Reserved_15 : 56|8@1+ (1,0) [0|255] ""  IMM

BO_ 2332111776 M2I_Byrack_SUMDATA19__16: 8 MBMU
 SG_ CRC_M2I_Byrack_IMM19_16 : 0|8@1+ (1,0) [0|255] ""  IMM
 SG_ M2I_Byrack_HVS_IMM19_16 : 8|16@1+ (0.1,0) [0|6553.5] "v"  IMM
 SG_ M2I_Byrack_Enable_IMM9_16 : 24|2@1+ (1,0) [0|3] ""  IMM
 SG_ M2I_Byrack_ReVeEnable_IMM19_16 : 26|2@1+ (1,0) [0|3] ""  IMM
 SG_ Reserved_16 : 28|4@1+ (1,0) [0|15] ""  IMM
 SG_ M2I_Byrack_IsPostTm_IMM19_16 : 32|8@1+ (0.01,0) [0|2.55] "s"  IMM
 SG_ M2I_Byrack_SysABStTm_IMM19_16 : 40|16@1+ (0.01,0) [0|655.35] "s"  IMM
 SG_ Reserved_16 : 56|8@1+ (1,0) [0|255] ""  IMM

BO_ 2332111777 M2I_Byrack_SUMDATA19__17: 8 MBMU
 SG_ CRC_M2I_Byrack_IMM19_17 : 0|8@1+ (1,0) [0|255] ""  IMM
 SG_ M2I_Byrack_HVS_IMM19_17 : 8|16@1+ (0.1,0) [0|6553.5] "v"  IMM
 SG_ M2I_Byrack_Enable_IMM9_17 : 24|2@1+ (1,0) [0|3] ""  IMM
 SG_ M2I_Byrack_ReVeEnable_IMM19_17 : 26|2@1+ (1,0) [0|3] ""  IMM
 SG_ Reserved_17 : 28|4@1+ (1,0) [0|15] ""  IMM
 SG_ M2I_Byrack_IsPostTm_IMM19_17 : 32|8@1+ (0.01,0) [0|2.55] "s"  IMM
 SG_ M2I_Byrack_SysABStTm_IMM19_17 : 40|16@1+ (0.01,0) [0|655.35] "s"  IMM
 SG_ Reserved_17 : 56|8@1+ (1,0) [0|255] ""  IMM

BO_ 2332111778 M2I_Byrack_SUMDATA19__18: 8 MBMU
 SG_ CRC_M2I_Byrack_IMM19_18 : 0|8@1+ (1,0) [0|255] ""  IMM
 SG_ M2I_Byrack_HVS_IMM19_18 : 8|16@1+ (0.1,0) [0|6553.5] "v"  IMM
 SG_ M2I_Byrack_Enable_IMM9_18 : 24|2@1+ (1,0) [0|3] ""  IMM
 SG_ M2I_Byrack_ReVeEnable_IMM19_18 : 26|2@1+ (1,0) [0|3] ""  IMM
 SG_ Reserved_18 : 28|4@1+ (1,0) [0|15] ""  IMM
 SG_ M2I_Byrack_IsPostTm_IMM19_18 : 32|8@1+ (0.01,0) [0|2.55] "s"  IMM
 SG_ M2I_Byrack_SysABStTm_IMM19_18 : 40|16@1+ (0.01,0) [0|655.35] "s"  IMM
 SG_ Reserved_18 : 56|8@1+ (1,0) [0|255] ""  IMM

BO_ 2332111779 M2I_Byrack_SUMDATA19__19: 8 MBMU
 SG_ CRC_M2I_Byrack_IMM19_19 : 0|8@1+ (1,0) [0|255] ""  IMM
 SG_ M2I_Byrack_HVS_IMM19_19 : 8|16@1+ (0.1,0) [0|6553.5] "v"  IMM
 SG_ M2I_Byrack_Enable_IMM9_19 : 24|2@1+ (1,0) [0|3] ""  IMM
 SG_ M2I_Byrack_ReVeEnable_IMM19_19 : 26|2@1+ (1,0) [0|3] ""  IMM
 SG_ Reserved_19 : 28|4@1+ (1,0) [0|15] ""  IMM
 SG_ M2I_Byrack_IsPostTm_IMM19_19 : 32|8@1+ (0.01,0) [0|2.55] "s"  IMM
 SG_ M2I_Byrack_SysABStTm_IMM19_19 : 40|16@1+ (0.01,0) [0|655.35] "s"  IMM
 SG_ Reserved_19 : 56|8@1+ (1,0) [0|255] ""  IMM

BO_ 2332111780 M2I_Byrack_SUMDATA19__20: 8 MBMU
 SG_ CRC_M2I_Byrack_IMM19_20 : 0|8@1+ (1,0) [0|255] ""  IMM
 SG_ M2I_Byrack_HVS_IMM19_20 : 8|16@1+ (0.1,0) [0|6553.5] "v"  IMM
 SG_ M2I_Byrack_Enable_IMM9_20 : 24|2@1+ (1,0) [0|3] ""  IMM
 SG_ M2I_Byrack_ReVeEnable_IMM19_20 : 26|2@1+ (1,0) [0|3] ""  IMM
 SG_ Reserved_20 : 28|4@1+ (1,0) [0|15] ""  IMM
 SG_ M2I_Byrack_IsPostTm_IMM19_20 : 32|8@1+ (0.01,0) [0|2.55] "s"  IMM
 SG_ M2I_Byrack_SysABStTm_IMM19_20 : 40|16@1+ (0.01,0) [0|655.35] "s"  IMM
 SG_ Reserved_20 : 56|8@1+ (1,0) [0|255] ""  IMM

BO_ 2332111781 M2I_Byrack_SUMDATA19__21: 8 MBMU
 SG_ CRC_M2I_Byrack_IMM19_21 : 0|8@1+ (1,0) [0|255] ""  IMM
 SG_ M2I_Byrack_HVS_IMM19_21 : 8|16@1+ (0.1,0) [0|6553.5] "v"  IMM
 SG_ M2I_Byrack_Enable_IMM9_21 : 24|2@1+ (1,0) [0|3] ""  IMM
 SG_ M2I_Byrack_ReVeEnable_IMM19_21 : 26|2@1+ (1,0) [0|3] ""  IMM
 SG_ Reserved_21 : 28|4@1+ (1,0) [0|15] ""  IMM
 SG_ M2I_Byrack_IsPostTm_IMM19_21 : 32|8@1+ (0.01,0) [0|2.55] "s"  IMM
 SG_ M2I_Byrack_SysABStTm_IMM19_21 : 40|16@1+ (0.01,0) [0|655.35] "s"  IMM
 SG_ Reserved_21 : 56|8@1+ (1,0) [0|255] ""  IMM

BO_ 2332111782 M2I_Byrack_SUMDATA19__22: 8 MBMU
 SG_ CRC_M2I_Byrack_IMM19_22 : 0|8@1+ (1,0) [0|255] ""  IMM
 SG_ M2I_Byrack_HVS_IMM19_22 : 8|16@1+ (0.1,0) [0|6553.5] "v"  IMM
 SG_ M2I_Byrack_Enable_IMM9_22 : 24|2@1+ (1,0) [0|3] ""  IMM
 SG_ M2I_Byrack_ReVeEnable_IMM19_22 : 26|2@1+ (1,0) [0|3] ""  IMM
 SG_ Reserved_22 : 28|4@1+ (1,0) [0|15] ""  IMM
 SG_ M2I_Byrack_IsPostTm_IMM19_22 : 32|8@1+ (0.01,0) [0|2.55] "s"  IMM
 SG_ M2I_Byrack_SysABStTm_IMM19_22 : 40|16@1+ (0.01,0) [0|655.35] "s"  IMM
 SG_ Reserved_22 : 56|8@1+ (1,0) [0|255] ""  IMM

BO_ 2332111783 M2I_Byrack_SUMDATA19__23: 8 MBMU
 SG_ CRC_M2I_Byrack_IMM19_23 : 0|8@1+ (1,0) [0|255] ""  IMM
 SG_ M2I_Byrack_HVS_IMM19_23 : 8|16@1+ (0.1,0) [0|6553.5] "v"  IMM
 SG_ M2I_Byrack_Enable_IMM9_23 : 24|2@1+ (1,0) [0|3] ""  IMM
 SG_ M2I_Byrack_ReVeEnable_IMM19_23 : 26|2@1+ (1,0) [0|3] ""  IMM
 SG_ Reserved_23 : 28|4@1+ (1,0) [0|15] ""  IMM
 SG_ M2I_Byrack_IsPostTm_IMM19_23 : 32|8@1+ (0.01,0) [0|2.55] "s"  IMM
 SG_ M2I_Byrack_SysABStTm_IMM19_23 : 40|16@1+ (0.01,0) [0|655.35] "s"  IMM
 SG_ Reserved_23 : 56|8@1+ (1,0) [0|255] ""  IMM

BO_ 2332111784 M2I_Byrack_SUMDATA19__24: 8 MBMU
 SG_ CRC_M2I_Byrack_IMM19_24 : 0|8@1+ (1,0) [0|255] ""  IMM
 SG_ M2I_Byrack_HVS_IMM19_24 : 8|16@1+ (0.1,0) [0|6553.5] "v"  IMM
 SG_ M2I_Byrack_Enable_IMM9_24 : 24|2@1+ (1,0) [0|3] ""  IMM
 SG_ M2I_Byrack_ReVeEnable_IMM19_24 : 26|2@1+ (1,0) [0|3] ""  IMM
 SG_ Reserved_24 : 28|4@1+ (1,0) [0|15] ""  IMM
 SG_ M2I_Byrack_IsPostTm_IMM19_24 : 32|8@1+ (0.01,0) [0|2.55] "s"  IMM
 SG_ M2I_Byrack_SysABStTm_IMM19_24 : 40|16@1+ (0.01,0) [0|655.35] "s"  IMM
 SG_ Reserved_24 : 56|8@1+ (1,0) [0|255] ""  IMM

BO_ 2332111785 M2I_Byrack_SUMDATA19__25: 8 MBMU
 SG_ CRC_M2I_Byrack_IMM19_25 : 0|8@1+ (1,0) [0|255] ""  IMM
 SG_ M2I_Byrack_HVS_IMM19_25 : 8|16@1+ (0.1,0) [0|6553.5] "v"  IMM
 SG_ M2I_Byrack_Enable_IMM9_25 : 24|2@1+ (1,0) [0|3] ""  IMM
 SG_ M2I_Byrack_ReVeEnable_IMM19_25 : 26|2@1+ (1,0) [0|3] ""  IMM
 SG_ Reserved_25 : 28|4@1+ (1,0) [0|15] ""  IMM
 SG_ M2I_Byrack_IsPostTm_IMM19_25 : 32|8@1+ (0.01,0) [0|2.55] "s"  IMM
 SG_ M2I_Byrack_SysABStTm_IMM19_25 : 40|16@1+ (0.01,0) [0|655.35] "s"  IMM
 SG_ Reserved_25 : 56|8@1+ (1,0) [0|255] ""  IMM

BO_ 2332111786 M2I_Byrack_SUMDATA19__26: 8 MBMU
 SG_ CRC_M2I_Byrack_IMM19_26 : 0|8@1+ (1,0) [0|255] ""  IMM
 SG_ M2I_Byrack_HVS_IMM19_26 : 8|16@1+ (0.1,0) [0|6553.5] "v"  IMM
 SG_ M2I_Byrack_Enable_IMM9_26 : 24|2@1+ (1,0) [0|3] ""  IMM
 SG_ M2I_Byrack_ReVeEnable_IMM19_26 : 26|2@1+ (1,0) [0|3] ""  IMM
 SG_ Reserved_26 : 28|4@1+ (1,0) [0|15] ""  IMM
 SG_ M2I_Byrack_IsPostTm_IMM19_26 : 32|8@1+ (0.01,0) [0|2.55] "s"  IMM
 SG_ M2I_Byrack_SysABStTm_IMM19_26 : 40|16@1+ (0.01,0) [0|655.35] "s"  IMM
 SG_ Reserved_26 : 56|8@1+ (1,0) [0|255] ""  IMM

BO_ 2332111787 M2I_Byrack_SUMDATA19__27: 8 MBMU
 SG_ CRC_M2I_Byrack_IMM19_27 : 0|8@1+ (1,0) [0|255] ""  IMM
 SG_ M2I_Byrack_HVS_IMM19_27 : 8|16@1+ (0.1,0) [0|6553.5] "v"  IMM
 SG_ M2I_Byrack_Enable_IMM9_27 : 24|2@1+ (1,0) [0|3] ""  IMM
 SG_ M2I_Byrack_ReVeEnable_IMM19_27 : 26|2@1+ (1,0) [0|3] ""  IMM
 SG_ Reserved_27 : 28|4@1+ (1,0) [0|15] ""  IMM
 SG_ M2I_Byrack_IsPostTm_IMM19_27 : 32|8@1+ (0.01,0) [0|2.55] "s"  IMM
 SG_ M2I_Byrack_SysABStTm_IMM19_27 : 40|16@1+ (0.01,0) [0|655.35] "s"  IMM
 SG_ Reserved_27 : 56|8@1+ (1,0) [0|255] ""  IMM

BO_ 2332111788 M2I_Byrack_SUMDATA19__28: 8 MBMU
 SG_ CRC_M2I_Byrack_IMM19_28 : 0|8@1+ (1,0) [0|255] ""  IMM
 SG_ M2I_Byrack_HVS_IMM19_28 : 8|16@1+ (0.1,0) [0|6553.5] "v"  IMM
 SG_ M2I_Byrack_Enable_IMM9_28 : 24|2@1+ (1,0) [0|3] ""  IMM
 SG_ M2I_Byrack_ReVeEnable_IMM19_28 : 26|2@1+ (1,0) [0|3] ""  IMM
 SG_ Reserved_28 : 28|4@1+ (1,0) [0|15] ""  IMM
 SG_ M2I_Byrack_IsPostTm_IMM19_28 : 32|8@1+ (0.01,0) [0|2.55] "s"  IMM
 SG_ M2I_Byrack_SysABStTm_IMM19_28 : 40|16@1+ (0.01,0) [0|655.35] "s"  IMM
 SG_ Reserved_28 : 56|8@1+ (1,0) [0|255] ""  IMM

BO_ 2332111789 M2I_Byrack_SUMDATA19__29: 8 MBMU
 SG_ CRC_M2I_Byrack_IMM19_29 : 0|8@1+ (1,0) [0|255] ""  IMM
 SG_ M2I_Byrack_HVS_IMM19_29 : 8|16@1+ (0.1,0) [0|6553.5] "v"  IMM
 SG_ M2I_Byrack_Enable_IMM9_29 : 24|2@1+ (1,0) [0|3] ""  IMM
 SG_ M2I_Byrack_ReVeEnable_IMM19_29 : 26|2@1+ (1,0) [0|3] ""  IMM
 SG_ Reserved_29 : 28|4@1+ (1,0) [0|15] ""  IMM
 SG_ M2I_Byrack_IsPostTm_IMM19_29 : 32|8@1+ (0.01,0) [0|2.55] "s"  IMM
 SG_ M2I_Byrack_SysABStTm_IMM19_29 : 40|16@1+ (0.01,0) [0|655.35] "s"  IMM
 SG_ Reserved_29 : 56|8@1+ (1,0) [0|255] ""  IMM

BO_ 2332111790 M2I_Byrack_SUMDATA19__30: 8 MBMU
 SG_ CRC_M2I_Byrack_IMM19_30 : 0|8@1+ (1,0) [0|255] ""  IMM
 SG_ M2I_Byrack_HVS_IMM19_30 : 8|16@1+ (0.1,0) [0|6553.5] "v"  IMM
 SG_ M2I_Byrack_Enable_IMM9_30 : 24|2@1+ (1,0) [0|3] ""  IMM
 SG_ M2I_Byrack_ReVeEnable_IMM19_30 : 26|2@1+ (1,0) [0|3] ""  IMM
 SG_ Reserved_30 : 28|4@1+ (1,0) [0|15] ""  IMM
 SG_ M2I_Byrack_IsPostTm_IMM19_30 : 32|8@1+ (0.01,0) [0|2.55] "s"  IMM
 SG_ M2I_Byrack_SysABStTm_IMM19_30 : 40|16@1+ (0.01,0) [0|655.35] "s"  IMM
 SG_ Reserved_30 : 56|8@1+ (1,0) [0|255] ""  IMM

BO_ 2332111791 M2I_Byrack_SUMDATA19__31: 8 MBMU
 SG_ CRC_M2I_Byrack_IMM19_31 : 0|8@1+ (1,0) [0|255] ""  IMM
 SG_ M2I_Byrack_HVS_IMM19_31 : 8|16@1+ (0.1,0) [0|6553.5] "v"  IMM
 SG_ M2I_Byrack_Enable_IMM9_31 : 24|2@1+ (1,0) [0|3] ""  IMM
 SG_ M2I_Byrack_ReVeEnable_IMM19_31 : 26|2@1+ (1,0) [0|3] ""  IMM
 SG_ Reserved_31 : 28|4@1+ (1,0) [0|15] ""  IMM
 SG_ M2I_Byrack_IsPostTm_IMM19_31 : 32|8@1+ (0.01,0) [0|2.55] "s"  IMM
 SG_ M2I_Byrack_SysABStTm_IMM19_31 : 40|16@1+ (0.01,0) [0|655.35] "s"  IMM
 SG_ Reserved_31 : 56|8@1+ (1,0) [0|255] ""  IMM

BO_ 2332112017 M2I_Byrack_SUMDATA20__01: 8 MBMU
 SG_ CRC_M2I_Byrack_IMM20_01 : 0|8@1+ (1,0) [0|255] ""  IMM
 SG_ M2I_Byrack_HVS_IMM20_01 : 8|16@1+ (0.1,0) [0|6553.5] "v"  IMM
 SG_ M2I_Byrack_Enable_IMM20_01 : 24|2@1+ (1,0) [0|3] ""  IMM
 SG_ M2I_Byrack_ReVeEnable_IMM20_01 : 26|2@1+ (1,0) [0|3] ""  IMM
 SG_ Reserved_01 : 28|4@1+ (1,0) [0|15] ""  IMM
 SG_ M2I_Byrack_IsPostTm_IMM20_01 : 32|8@1+ (0.01,0) [0|2.55] "s"  IMM
 SG_ M2I_Byrack_SysABStTm_IMM20_01 : 40|16@1+ (0.01,0) [0|655.35] "s"  IMM
 SG_ Reserved_01 : 56|8@1+ (1,0) [0|255] ""  IMM

BO_ 2332112018 M2I_Byrack_SUMDATA20__02: 8 MBMU
 SG_ CRC_M2I_Byrack_IMM20_02 : 0|8@1+ (1,0) [0|255] ""  IMM
 SG_ M2I_Byrack_HVS_IMM20_02 : 8|16@1+ (0.1,0) [0|6553.5] "v"  IMM
 SG_ M2I_Byrack_Enable_IMM20_02 : 24|2@1+ (1,0) [0|3] ""  IMM
 SG_ M2I_Byrack_ReVeEnable_IMM20_02 : 26|2@1+ (1,0) [0|3] ""  IMM
 SG_ Reserved_02 : 28|4@1+ (1,0) [0|15] ""  IMM
 SG_ M2I_Byrack_IsPostTm_IMM20_02 : 32|8@1+ (0.01,0) [0|2.55] "s"  IMM
 SG_ M2I_Byrack_SysABStTm_IMM20_02 : 40|16@1+ (0.01,0) [0|655.35] "s"  IMM
 SG_ Reserved_02 : 56|8@1+ (1,0) [0|255] ""  IMM

BO_ 2332112019 M2I_Byrack_SUMDATA20__03: 8 MBMU
 SG_ CRC_M2I_Byrack_IMM20_03 : 0|8@1+ (1,0) [0|255] ""  IMM
 SG_ M2I_Byrack_HVS_IMM20_03 : 8|16@1+ (0.1,0) [0|6553.5] "v"  IMM
 SG_ M2I_Byrack_Enable_IMM20_03 : 24|2@1+ (1,0) [0|3] ""  IMM
 SG_ M2I_Byrack_ReVeEnable_IMM20_03 : 26|2@1+ (1,0) [0|3] ""  IMM
 SG_ Reserved_03 : 28|4@1+ (1,0) [0|15] ""  IMM
 SG_ M2I_Byrack_IsPostTm_IMM20_03 : 32|8@1+ (0.01,0) [0|2.55] "s"  IMM
 SG_ M2I_Byrack_SysABStTm_IMM20_03 : 40|16@1+ (0.01,0) [0|655.35] "s"  IMM
 SG_ Reserved_03 : 56|8@1+ (1,0) [0|255] ""  IMM

BO_ 2332112020 M2I_Byrack_SUMDATA20__04: 8 MBMU
 SG_ CRC_M2I_Byrack_IMM20_04 : 0|8@1+ (1,0) [0|255] ""  IMM
 SG_ M2I_Byrack_HVS_IMM20_04 : 8|16@1+ (0.1,0) [0|6553.5] "v"  IMM
 SG_ M2I_Byrack_Enable_IMM20_04 : 24|2@1+ (1,0) [0|3] ""  IMM
 SG_ M2I_Byrack_ReVeEnable_IMM20_04 : 26|2@1+ (1,0) [0|3] ""  IMM
 SG_ Reserved_04 : 28|4@1+ (1,0) [0|15] ""  IMM
 SG_ M2I_Byrack_IsPostTm_IMM20_04 : 32|8@1+ (0.01,0) [0|2.55] "s"  IMM
 SG_ M2I_Byrack_SysABStTm_IMM20_04 : 40|16@1+ (0.01,0) [0|655.35] "s"  IMM
 SG_ Reserved_04 : 56|8@1+ (1,0) [0|255] ""  IMM

BO_ 2332112021 M2I_Byrack_SUMDATA20__05: 8 MBMU
 SG_ CRC_M2I_Byrack_IMM20_05 : 0|8@1+ (1,0) [0|255] ""  IMM
 SG_ M2I_Byrack_HVS_IMM20_05 : 8|16@1+ (0.1,0) [0|6553.5] "v"  IMM
 SG_ M2I_Byrack_Enable_IMM20_05 : 24|2@1+ (1,0) [0|3] ""  IMM
 SG_ M2I_Byrack_ReVeEnable_IMM20_05 : 26|2@1+ (1,0) [0|3] ""  IMM
 SG_ Reserved_05 : 28|4@1+ (1,0) [0|15] ""  IMM
 SG_ M2I_Byrack_IsPostTm_IMM20_05 : 32|8@1+ (0.01,0) [0|2.55] "s"  IMM
 SG_ M2I_Byrack_SysABStTm_IMM20_05 : 40|16@1+ (0.01,0) [0|655.35] "s"  IMM
 SG_ Reserved_05 : 56|8@1+ (1,0) [0|255] ""  IMM

BO_ 2332112022 M2I_Byrack_SUMDATA20__06: 8 MBMU
 SG_ CRC_M2I_Byrack_IMM20_06 : 0|8@1+ (1,0) [0|255] ""  IMM
 SG_ M2I_Byrack_HVS_IMM20_06 : 8|16@1+ (0.1,0) [0|6553.5] "v"  IMM
 SG_ M2I_Byrack_Enable_IMM20_06 : 24|2@1+ (1,0) [0|3] ""  IMM
 SG_ M2I_Byrack_ReVeEnable_IMM20_06 : 26|2@1+ (1,0) [0|3] ""  IMM
 SG_ Reserved_06 : 28|4@1+ (1,0) [0|15] ""  IMM
 SG_ M2I_Byrack_IsPostTm_IMM20_06 : 32|8@1+ (0.01,0) [0|2.55] "s"  IMM
 SG_ M2I_Byrack_SysABStTm_IMM20_06 : 40|16@1+ (0.01,0) [0|655.35] "s"  IMM
 SG_ Reserved_06 : 56|8@1+ (1,0) [0|255] ""  IMM

BO_ 2332112023 M2I_Byrack_SUMDATA20__07: 8 MBMU
 SG_ CRC_M2I_Byrack_IMM20_07 : 0|8@1+ (1,0) [0|255] ""  IMM
 SG_ M2I_Byrack_HVS_IMM20_07 : 8|16@1+ (0.1,0) [0|6553.5] "v"  IMM
 SG_ M2I_Byrack_Enable_IMM20_07 : 24|2@1+ (1,0) [0|3] ""  IMM
 SG_ M2I_Byrack_ReVeEnable_IMM20_07 : 26|2@1+ (1,0) [0|3] ""  IMM
 SG_ Reserved_07 : 28|4@1+ (1,0) [0|15] ""  IMM
 SG_ M2I_Byrack_IsPostTm_IMM20_07 : 32|8@1+ (0.01,0) [0|2.55] "s"  IMM
 SG_ M2I_Byrack_SysABStTm_IMM20_07 : 40|16@1+ (0.01,0) [0|655.35] "s"  IMM
 SG_ Reserved_07 : 56|8@1+ (1,0) [0|255] ""  IMM

BO_ 2332112024 M2I_Byrack_SUMDATA20__08: 8 MBMU
 SG_ CRC_M2I_Byrack_IMM20_08 : 0|8@1+ (1,0) [0|255] ""  IMM
 SG_ M2I_Byrack_HVS_IMM20_08 : 8|16@1+ (0.1,0) [0|6553.5] "v"  IMM
 SG_ M2I_Byrack_Enable_IMM20_08 : 24|2@1+ (1,0) [0|3] ""  IMM
 SG_ M2I_Byrack_ReVeEnable_IMM20_08 : 26|2@1+ (1,0) [0|3] ""  IMM
 SG_ Reserved_08 : 28|4@1+ (1,0) [0|15] ""  IMM
 SG_ M2I_Byrack_IsPostTm_IMM20_08 : 32|8@1+ (0.01,0) [0|2.55] "s"  IMM
 SG_ M2I_Byrack_SysABStTm_IMM20_08 : 40|16@1+ (0.01,0) [0|655.35] "s"  IMM
 SG_ Reserved_08 : 56|8@1+ (1,0) [0|255] ""  IMM

BO_ 2332112025 M2I_Byrack_SUMDATA20__09: 8 MBMU
 SG_ CRC_M2I_Byrack_IMM20_09 : 0|8@1+ (1,0) [0|255] ""  IMM
 SG_ M2I_Byrack_HVS_IMM20_09 : 8|16@1+ (0.1,0) [0|6553.5] "v"  IMM
 SG_ M2I_Byrack_Enable_IMM20_09 : 24|2@1+ (1,0) [0|3] ""  IMM
 SG_ M2I_Byrack_ReVeEnable_IMM20_09 : 26|2@1+ (1,0) [0|3] ""  IMM
 SG_ Reserved_09 : 28|4@1+ (1,0) [0|15] ""  IMM
 SG_ M2I_Byrack_IsPostTm_IMM20_09 : 32|8@1+ (0.01,0) [0|2.55] "s"  IMM
 SG_ M2I_Byrack_SysABStTm_IMM20_09 : 40|16@1+ (0.01,0) [0|655.35] "s"  IMM
 SG_ Reserved_09 : 56|8@1+ (1,0) [0|255] ""  IMM

BO_ 2332112026 M2I_Byrack_SUMDATA20__10: 8 MBMU
 SG_ CRC_M2I_Byrack_IMM20_10 : 0|8@1+ (1,0) [0|255] ""  IMM
 SG_ M2I_Byrack_HVS_IMM20_10 : 8|16@1+ (0.1,0) [0|6553.5] "v"  IMM
 SG_ M2I_Byrack_Enable_IMM20_10 : 24|2@1+ (1,0) [0|3] ""  IMM
 SG_ M2I_Byrack_ReVeEnable_IMM20_10 : 26|2@1+ (1,0) [0|3] ""  IMM
 SG_ Reserved_10 : 28|4@1+ (1,0) [0|15] ""  IMM
 SG_ M2I_Byrack_IsPostTm_IMM20_10 : 32|8@1+ (0.01,0) [0|2.55] "s"  IMM
 SG_ M2I_Byrack_SysABStTm_IMM20_10 : 40|16@1+ (0.01,0) [0|655.35] "s"  IMM
 SG_ Reserved_10 : 56|8@1+ (1,0) [0|255] ""  IMM

BO_ 2332112027 M2I_Byrack_SUMDATA20__11: 8 MBMU
 SG_ CRC_M2I_Byrack_IMM20_11 : 0|8@1+ (1,0) [0|255] ""  IMM
 SG_ M2I_Byrack_HVS_IMM20_11 : 8|16@1+ (0.1,0) [0|6553.5] "v"  IMM
 SG_ M2I_Byrack_Enable_IMM20_11 : 24|2@1+ (1,0) [0|3] ""  IMM
 SG_ M2I_Byrack_ReVeEnable_IMM20_11 : 26|2@1+ (1,0) [0|3] ""  IMM
 SG_ Reserved_11 : 28|4@1+ (1,0) [0|15] ""  IMM
 SG_ M2I_Byrack_IsPostTm_IMM20_11 : 32|8@1+ (0.01,0) [0|2.55] "s"  IMM
 SG_ M2I_Byrack_SysABStTm_IMM20_11 : 40|16@1+ (0.01,0) [0|655.35] "s"  IMM
 SG_ Reserved_11 : 56|8@1+ (1,0) [0|255] ""  IMM

BO_ 2332112028 M2I_Byrack_SUMDATA20__12: 8 MBMU
 SG_ CRC_M2I_Byrack_IMM20_12 : 0|8@1+ (1,0) [0|255] ""  IMM
 SG_ M2I_Byrack_HVS_IMM20_12 : 8|16@1+ (0.1,0) [0|6553.5] "v"  IMM
 SG_ M2I_Byrack_Enable_IMM20_12 : 24|2@1+ (1,0) [0|3] ""  IMM
 SG_ M2I_Byrack_ReVeEnable_IMM20_12 : 26|2@1+ (1,0) [0|3] ""  IMM
 SG_ Reserved_12 : 28|4@1+ (1,0) [0|15] ""  IMM
 SG_ M2I_Byrack_IsPostTm_IMM20_12 : 32|8@1+ (0.01,0) [0|2.55] "s"  IMM
 SG_ M2I_Byrack_SysABStTm_IMM20_12 : 40|16@1+ (0.01,0) [0|655.35] "s"  IMM
 SG_ Reserved_12 : 56|8@1+ (1,0) [0|255] ""  IMM

BO_ 2332112029 M2I_Byrack_SUMDATA20__13: 8 MBMU
 SG_ CRC_M2I_Byrack_IMM20_13 : 0|8@1+ (1,0) [0|255] ""  IMM
 SG_ M2I_Byrack_HVS_IMM20_13 : 8|16@1+ (0.1,0) [0|6553.5] "v"  IMM
 SG_ M2I_Byrack_Enable_IMM20_13 : 24|2@1+ (1,0) [0|3] ""  IMM
 SG_ M2I_Byrack_ReVeEnable_IMM20_13 : 26|2@1+ (1,0) [0|3] ""  IMM
 SG_ Reserved_13 : 28|4@1+ (1,0) [0|15] ""  IMM
 SG_ M2I_Byrack_IsPostTm_IMM20_13 : 32|8@1+ (0.01,0) [0|2.55] "s"  IMM
 SG_ M2I_Byrack_SysABStTm_IMM20_13 : 40|16@1+ (0.01,0) [0|655.35] "s"  IMM
 SG_ Reserved_13 : 56|8@1+ (1,0) [0|255] ""  IMM

BO_ 2332112030 M2I_Byrack_SUMDATA20__14: 8 MBMU
 SG_ CRC_M2I_Byrack_IMM20_14 : 0|8@1+ (1,0) [0|255] ""  IMM
 SG_ M2I_Byrack_HVS_IMM20_14 : 8|16@1+ (0.1,0) [0|6553.5] "v"  IMM
 SG_ M2I_Byrack_Enable_IMM20_14 : 24|2@1+ (1,0) [0|3] ""  IMM
 SG_ M2I_Byrack_ReVeEnable_IMM20_14 : 26|2@1+ (1,0) [0|3] ""  IMM
 SG_ Reserved_14 : 28|4@1+ (1,0) [0|15] ""  IMM
 SG_ M2I_Byrack_IsPostTm_IMM20_14 : 32|8@1+ (0.01,0) [0|2.55] "s"  IMM
 SG_ M2I_Byrack_SysABStTm_IMM20_14 : 40|16@1+ (0.01,0) [0|655.35] "s"  IMM
 SG_ Reserved_14 : 56|8@1+ (1,0) [0|255] ""  IMM

BO_ 2332112031 M2I_Byrack_SUMDATA20__15: 8 MBMU
 SG_ CRC_M2I_Byrack_IMM20_15 : 0|8@1+ (1,0) [0|255] ""  IMM
 SG_ M2I_Byrack_HVS_IMM20_15 : 8|16@1+ (0.1,0) [0|6553.5] "v"  IMM
 SG_ M2I_Byrack_Enable_IMM20_15 : 24|2@1+ (1,0) [0|3] ""  IMM
 SG_ M2I_Byrack_ReVeEnable_IMM20_15 : 26|2@1+ (1,0) [0|3] ""  IMM
 SG_ Reserved_15 : 28|4@1+ (1,0) [0|15] ""  IMM
 SG_ M2I_Byrack_IsPostTm_IMM20_15 : 32|8@1+ (0.01,0) [0|2.55] "s"  IMM
 SG_ M2I_Byrack_SysABStTm_IMM20_15 : 40|16@1+ (0.01,0) [0|655.35] "s"  IMM
 SG_ Reserved_15 : 56|8@1+ (1,0) [0|255] ""  IMM

BO_ 2332112032 M2I_Byrack_SUMDATA20__16: 8 MBMU
 SG_ CRC_M2I_Byrack_IMM20_16 : 0|8@1+ (1,0) [0|255] ""  IMM
 SG_ M2I_Byrack_HVS_IMM20_16 : 8|16@1+ (0.1,0) [0|6553.5] "v"  IMM
 SG_ M2I_Byrack_Enable_IMM20_16 : 24|2@1+ (1,0) [0|3] ""  IMM
 SG_ M2I_Byrack_ReVeEnable_IMM20_16 : 26|2@1+ (1,0) [0|3] ""  IMM
 SG_ Reserved_16 : 28|4@1+ (1,0) [0|15] ""  IMM
 SG_ M2I_Byrack_IsPostTm_IMM20_16 : 32|8@1+ (0.01,0) [0|2.55] "s"  IMM
 SG_ M2I_Byrack_SysABStTm_IMM20_16 : 40|16@1+ (0.01,0) [0|655.35] "s"  IMM
 SG_ Reserved_16 : 56|8@1+ (1,0) [0|255] ""  IMM

BO_ 2332112033 M2I_Byrack_SUMDATA20__17: 8 MBMU
 SG_ CRC_M2I_Byrack_IMM20_17 : 0|8@1+ (1,0) [0|255] ""  IMM
 SG_ M2I_Byrack_HVS_IMM20_17 : 8|16@1+ (0.1,0) [0|6553.5] "v"  IMM
 SG_ M2I_Byrack_Enable_IMM20_17 : 24|2@1+ (1,0) [0|3] ""  IMM
 SG_ M2I_Byrack_ReVeEnable_IMM20_17 : 26|2@1+ (1,0) [0|3] ""  IMM
 SG_ Reserved_17 : 28|4@1+ (1,0) [0|15] ""  IMM
 SG_ M2I_Byrack_IsPostTm_IMM20_17 : 32|8@1+ (0.01,0) [0|2.55] "s"  IMM
 SG_ M2I_Byrack_SysABStTm_IMM20_17 : 40|16@1+ (0.01,0) [0|655.35] "s"  IMM
 SG_ Reserved_17 : 56|8@1+ (1,0) [0|255] ""  IMM

BO_ 2332112034 M2I_Byrack_SUMDATA20__18: 8 MBMU
 SG_ CRC_M2I_Byrack_IMM20_18 : 0|8@1+ (1,0) [0|255] ""  IMM
 SG_ M2I_Byrack_HVS_IMM20_18 : 8|16@1+ (0.1,0) [0|6553.5] "v"  IMM
 SG_ M2I_Byrack_Enable_IMM20_18 : 24|2@1+ (1,0) [0|3] ""  IMM
 SG_ M2I_Byrack_ReVeEnable_IMM20_18 : 26|2@1+ (1,0) [0|3] ""  IMM
 SG_ Reserved_18 : 28|4@1+ (1,0) [0|15] ""  IMM
 SG_ M2I_Byrack_IsPostTm_IMM20_18 : 32|8@1+ (0.01,0) [0|2.55] "s"  IMM
 SG_ M2I_Byrack_SysABStTm_IMM20_18 : 40|16@1+ (0.01,0) [0|655.35] "s"  IMM
 SG_ Reserved_18 : 56|8@1+ (1,0) [0|255] ""  IMM

BO_ 2332112035 M2I_Byrack_SUMDATA20__19: 8 MBMU
 SG_ CRC_M2I_Byrack_IMM20_19 : 0|8@1+ (1,0) [0|255] ""  IMM
 SG_ M2I_Byrack_HVS_IMM20_19 : 8|16@1+ (0.1,0) [0|6553.5] "v"  IMM
 SG_ M2I_Byrack_Enable_IMM20_19 : 24|2@1+ (1,0) [0|3] ""  IMM
 SG_ M2I_Byrack_ReVeEnable_IMM20_19 : 26|2@1+ (1,0) [0|3] ""  IMM
 SG_ Reserved_19 : 28|4@1+ (1,0) [0|15] ""  IMM
 SG_ M2I_Byrack_IsPostTm_IMM20_19 : 32|8@1+ (0.01,0) [0|2.55] "s"  IMM
 SG_ M2I_Byrack_SysABStTm_IMM20_19 : 40|16@1+ (0.01,0) [0|655.35] "s"  IMM
 SG_ Reserved_19 : 56|8@1+ (1,0) [0|255] ""  IMM

BO_ 2332112036 M2I_Byrack_SUMDATA20__20: 8 MBMU
 SG_ CRC_M2I_Byrack_IMM20_20 : 0|8@1+ (1,0) [0|255] ""  IMM
 SG_ M2I_Byrack_HVS_IMM20_20 : 8|16@1+ (0.1,0) [0|6553.5] "v"  IMM
 SG_ M2I_Byrack_Enable_IMM20_20 : 24|2@1+ (1,0) [0|3] ""  IMM
 SG_ M2I_Byrack_ReVeEnable_IMM20_20 : 26|2@1+ (1,0) [0|3] ""  IMM
 SG_ Reserved_20 : 28|4@1+ (1,0) [0|15] ""  IMM
 SG_ M2I_Byrack_IsPostTm_IMM20_20 : 32|8@1+ (0.01,0) [0|2.55] "s"  IMM
 SG_ M2I_Byrack_SysABStTm_IMM20_20 : 40|16@1+ (0.01,0) [0|655.35] "s"  IMM
 SG_ Reserved_20 : 56|8@1+ (1,0) [0|255] ""  IMM

BO_ 2332112037 M2I_Byrack_SUMDATA20__21: 8 MBMU
 SG_ CRC_M2I_Byrack_IMM20_21 : 0|8@1+ (1,0) [0|255] ""  IMM
 SG_ M2I_Byrack_HVS_IMM20_21 : 8|16@1+ (0.1,0) [0|6553.5] "v"  IMM
 SG_ M2I_Byrack_Enable_IMM20_21 : 24|2@1+ (1,0) [0|3] ""  IMM
 SG_ M2I_Byrack_ReVeEnable_IMM20_21 : 26|2@1+ (1,0) [0|3] ""  IMM
 SG_ Reserved_21 : 28|4@1+ (1,0) [0|15] ""  IMM
 SG_ M2I_Byrack_IsPostTm_IMM20_21 : 32|8@1+ (0.01,0) [0|2.55] "s"  IMM
 SG_ M2I_Byrack_SysABStTm_IMM20_21 : 40|16@1+ (0.01,0) [0|655.35] "s"  IMM
 SG_ Reserved_21 : 56|8@1+ (1,0) [0|255] ""  IMM

BO_ 2332112038 M2I_Byrack_SUMDATA20__22: 8 MBMU
 SG_ CRC_M2I_Byrack_IMM20_22 : 0|8@1+ (1,0) [0|255] ""  IMM
 SG_ M2I_Byrack_HVS_IMM20_22 : 8|16@1+ (0.1,0) [0|6553.5] "v"  IMM
 SG_ M2I_Byrack_Enable_IMM20_22 : 24|2@1+ (1,0) [0|3] ""  IMM
 SG_ M2I_Byrack_ReVeEnable_IMM20_22 : 26|2@1+ (1,0) [0|3] ""  IMM
 SG_ Reserved_22 : 28|4@1+ (1,0) [0|15] ""  IMM
 SG_ M2I_Byrack_IsPostTm_IMM20_22 : 32|8@1+ (0.01,0) [0|2.55] "s"  IMM
 SG_ M2I_Byrack_SysABStTm_IMM20_22 : 40|16@1+ (0.01,0) [0|655.35] "s"  IMM
 SG_ Reserved_22 : 56|8@1+ (1,0) [0|255] ""  IMM

BO_ 2332112039 M2I_Byrack_SUMDATA20__23: 8 MBMU
 SG_ CRC_M2I_Byrack_IMM20_23 : 0|8@1+ (1,0) [0|255] ""  IMM
 SG_ M2I_Byrack_HVS_IMM20_23 : 8|16@1+ (0.1,0) [0|6553.5] "v"  IMM
 SG_ M2I_Byrack_Enable_IMM20_23 : 24|2@1+ (1,0) [0|3] ""  IMM
 SG_ M2I_Byrack_ReVeEnable_IMM20_23 : 26|2@1+ (1,0) [0|3] ""  IMM
 SG_ Reserved_23 : 28|4@1+ (1,0) [0|15] ""  IMM
 SG_ M2I_Byrack_IsPostTm_IMM20_23 : 32|8@1+ (0.01,0) [0|2.55] "s"  IMM
 SG_ M2I_Byrack_SysABStTm_IMM20_23 : 40|16@1+ (0.01,0) [0|655.35] "s"  IMM
 SG_ Reserved_23 : 56|8@1+ (1,0) [0|255] ""  IMM

BO_ 2332112040 M2I_Byrack_SUMDATA20__24: 8 MBMU
 SG_ CRC_M2I_Byrack_IMM20_24 : 0|8@1+ (1,0) [0|255] ""  IMM
 SG_ M2I_Byrack_HVS_IMM20_24 : 8|16@1+ (0.1,0) [0|6553.5] "v"  IMM
 SG_ M2I_Byrack_Enable_IMM20_24 : 24|2@1+ (1,0) [0|3] ""  IMM
 SG_ M2I_Byrack_ReVeEnable_IMM20_24 : 26|2@1+ (1,0) [0|3] ""  IMM
 SG_ Reserved_24 : 28|4@1+ (1,0) [0|15] ""  IMM
 SG_ M2I_Byrack_IsPostTm_IMM20_24 : 32|8@1+ (0.01,0) [0|2.55] "s"  IMM
 SG_ M2I_Byrack_SysABStTm_IMM20_24 : 40|16@1+ (0.01,0) [0|655.35] "s"  IMM
 SG_ Reserved_24 : 56|8@1+ (1,0) [0|255] ""  IMM

BO_ 2332112041 M2I_Byrack_SUMDATA20__25: 8 MBMU
 SG_ CRC_M2I_Byrack_IMM20_25 : 0|8@1+ (1,0) [0|255] ""  IMM
 SG_ M2I_Byrack_HVS_IMM20_25 : 8|16@1+ (0.1,0) [0|6553.5] "v"  IMM
 SG_ M2I_Byrack_Enable_IMM20_25 : 24|2@1+ (1,0) [0|3] ""  IMM
 SG_ M2I_Byrack_ReVeEnable_IMM20_25 : 26|2@1+ (1,0) [0|3] ""  IMM
 SG_ Reserved_25 : 28|4@1+ (1,0) [0|15] ""  IMM
 SG_ M2I_Byrack_IsPostTm_IMM20_25 : 32|8@1+ (0.01,0) [0|2.55] "s"  IMM
 SG_ M2I_Byrack_SysABStTm_IMM20_25 : 40|16@1+ (0.01,0) [0|655.35] "s"  IMM
 SG_ Reserved_25 : 56|8@1+ (1,0) [0|255] ""  IMM

BO_ 2332112042 M2I_Byrack_SUMDATA20__26: 8 MBMU
 SG_ CRC_M2I_Byrack_IMM20_26 : 0|8@1+ (1,0) [0|255] ""  IMM
 SG_ M2I_Byrack_HVS_IMM20_26 : 8|16@1+ (0.1,0) [0|6553.5] "v"  IMM
 SG_ M2I_Byrack_Enable_IMM20_26 : 24|2@1+ (1,0) [0|3] ""  IMM
 SG_ M2I_Byrack_ReVeEnable_IMM20_26 : 26|2@1+ (1,0) [0|3] ""  IMM
 SG_ Reserved_26 : 28|4@1+ (1,0) [0|15] ""  IMM
 SG_ M2I_Byrack_IsPostTm_IMM20_26 : 32|8@1+ (0.01,0) [0|2.55] "s"  IMM
 SG_ M2I_Byrack_SysABStTm_IMM20_26 : 40|16@1+ (0.01,0) [0|655.35] "s"  IMM
 SG_ Reserved_26 : 56|8@1+ (1,0) [0|255] ""  IMM

BO_ 2332112043 M2I_Byrack_SUMDATA20__27: 8 MBMU
 SG_ CRC_M2I_Byrack_IMM20_27 : 0|8@1+ (1,0) [0|255] ""  IMM
 SG_ M2I_Byrack_HVS_IMM20_27 : 8|16@1+ (0.1,0) [0|6553.5] "v"  IMM
 SG_ M2I_Byrack_Enable_IMM20_27 : 24|2@1+ (1,0) [0|3] ""  IMM
 SG_ M2I_Byrack_ReVeEnable_IMM20_27 : 26|2@1+ (1,0) [0|3] ""  IMM
 SG_ Reserved_27 : 28|4@1+ (1,0) [0|15] ""  IMM
 SG_ M2I_Byrack_IsPostTm_IMM20_27 : 32|8@1+ (0.01,0) [0|2.55] "s"  IMM
 SG_ M2I_Byrack_SysABStTm_IMM20_27 : 40|16@1+ (0.01,0) [0|655.35] "s"  IMM
 SG_ Reserved_27 : 56|8@1+ (1,0) [0|255] ""  IMM

BO_ 2332112044 M2I_Byrack_SUMDATA20__28: 8 MBMU
 SG_ CRC_M2I_Byrack_IMM20_28 : 0|8@1+ (1,0) [0|255] ""  IMM
 SG_ M2I_Byrack_HVS_IMM20_28 : 8|16@1+ (0.1,0) [0|6553.5] "v"  IMM
 SG_ M2I_Byrack_Enable_IMM20_28 : 24|2@1+ (1,0) [0|3] ""  IMM
 SG_ M2I_Byrack_ReVeEnable_IMM20_28 : 26|2@1+ (1,0) [0|3] ""  IMM
 SG_ Reserved_28 : 28|4@1+ (1,0) [0|15] ""  IMM
 SG_ M2I_Byrack_IsPostTm_IMM20_28 : 32|8@1+ (0.01,0) [0|2.55] "s"  IMM
 SG_ M2I_Byrack_SysABStTm_IMM20_28 : 40|16@1+ (0.01,0) [0|655.35] "s"  IMM
 SG_ Reserved_28 : 56|8@1+ (1,0) [0|255] ""  IMM

BO_ 2332112045 M2I_Byrack_SUMDATA20__29: 8 MBMU
 SG_ CRC_M2I_Byrack_IMM20_29 : 0|8@1+ (1,0) [0|255] ""  IMM
 SG_ M2I_Byrack_HVS_IMM20_29 : 8|16@1+ (0.1,0) [0|6553.5] "v"  IMM
 SG_ M2I_Byrack_Enable_IMM20_29 : 24|2@1+ (1,0) [0|3] ""  IMM
 SG_ M2I_Byrack_ReVeEnable_IMM20_29 : 26|2@1+ (1,0) [0|3] ""  IMM
 SG_ Reserved_29 : 28|4@1+ (1,0) [0|15] ""  IMM
 SG_ M2I_Byrack_IsPostTm_IMM20_29 : 32|8@1+ (0.01,0) [0|2.55] "s"  IMM
 SG_ M2I_Byrack_SysABStTm_IMM20_29 : 40|16@1+ (0.01,0) [0|655.35] "s"  IMM
 SG_ Reserved_29 : 56|8@1+ (1,0) [0|255] ""  IMM

BO_ 2332112046 M2I_Byrack_SUMDATA20__30: 8 MBMU
 SG_ CRC_M2I_Byrack_IMM20_30 : 0|8@1+ (1,0) [0|255] ""  IMM
 SG_ M2I_Byrack_HVS_IMM20_30 : 8|16@1+ (0.1,0) [0|6553.5] "v"  IMM
 SG_ M2I_Byrack_Enable_IMM20_30 : 24|2@1+ (1,0) [0|3] ""  IMM
 SG_ M2I_Byrack_ReVeEnable_IMM20_30 : 26|2@1+ (1,0) [0|3] ""  IMM
 SG_ Reserved_30 : 28|4@1+ (1,0) [0|15] ""  IMM
 SG_ M2I_Byrack_IsPostTm_IMM20_30 : 32|8@1+ (0.01,0) [0|2.55] "s"  IMM
 SG_ M2I_Byrack_SysABStTm_IMM20_30 : 40|16@1+ (0.01,0) [0|655.35] "s"  IMM
 SG_ Reserved_30 : 56|8@1+ (1,0) [0|255] ""  IMM

BO_ 2332112047 M2I_Byrack_SUMDATA20__31: 8 MBMU
 SG_ CRC_M2I_Byrack_IMM20_31 : 0|8@1+ (1,0) [0|255] ""  IMM
 SG_ M2I_Byrack_HVS_IMM20_31 : 8|16@1+ (0.1,0) [0|6553.5] "v"  IMM
 SG_ M2I_Byrack_Enable_IMM20_31 : 24|2@1+ (1,0) [0|3] ""  IMM
 SG_ M2I_Byrack_ReVeEnable_IMM20_31 : 26|2@1+ (1,0) [0|3] ""  IMM
 SG_ Reserved_31 : 28|4@1+ (1,0) [0|15] ""  IMM
 SG_ M2I_Byrack_IsPostTm_IMM20_31 : 32|8@1+ (0.01,0) [0|2.55] "s"  IMM
 SG_ M2I_Byrack_SysABStTm_IMM20_31 : 40|16@1+ (0.01,0) [0|655.35] "s"  IMM
 SG_ Reserved_31 : 56|8@1+ (1,0) [0|255] ""  IMM

BO_ 2332112273 M2I_Byrack_SUMDATA21__01: 8 MBMU
 SG_ CRC_M2I_Byrack_IMM21_01 : 0|8@1+ (1,0) [0|255] ""  IMM
 SG_ M2I_Byrack_HVS_IMM21_01 : 8|16@1+ (0.1,0) [0|6553.5] "v"  IMM
 SG_ M2I_Byrack_Enable_IMM21_01 : 24|2@1+ (1,0) [0|3] ""  IMM
 SG_ M2I_Byrack_ReVeEnable_IMM21_01 : 26|2@1+ (1,0) [0|3] ""  IMM
 SG_ Reserved_01 : 28|4@1+ (1,0) [0|15] ""  IMM
 SG_ M2I_Byrack_IsPostTm_IMM21_01 : 32|8@1+ (0.01,0) [0|2.55] "s"  IMM
 SG_ M2I_Byrack_SysABStTm_IMM21_01 : 40|16@1+ (0.01,0) [0|655.35] "s"  IMM
 SG_ Reserved_01 : 56|8@1+ (1,0) [0|255] ""  IMM

BO_ 2332112274 M2I_Byrack_SUMDATA21__02: 8 MBMU
 SG_ CRC_M2I_Byrack_IMM21_02 : 0|8@1+ (1,0) [0|255] ""  IMM
 SG_ M2I_Byrack_HVS_IMM21_02 : 8|16@1+ (0.1,0) [0|6553.5] "v"  IMM
 SG_ M2I_Byrack_Enable_IMM21_02 : 24|2@1+ (1,0) [0|3] ""  IMM
 SG_ M2I_Byrack_ReVeEnable_IMM21_02 : 26|2@1+ (1,0) [0|3] ""  IMM
 SG_ Reserved_02 : 28|4@1+ (1,0) [0|15] ""  IMM
 SG_ M2I_Byrack_IsPostTm_IMM21_02 : 32|8@1+ (0.01,0) [0|2.55] "s"  IMM
 SG_ M2I_Byrack_SysABStTm_IMM21_02 : 40|16@1+ (0.01,0) [0|655.35] "s"  IMM
 SG_ Reserved_02 : 56|8@1+ (1,0) [0|255] ""  IMM

BO_ 2332112275 M2I_Byrack_SUMDATA21__03: 8 MBMU
 SG_ CRC_M2I_Byrack_IMM21_03 : 0|8@1+ (1,0) [0|255] ""  IMM
 SG_ M2I_Byrack_HVS_IMM21_03 : 8|16@1+ (0.1,0) [0|6553.5] "v"  IMM
 SG_ M2I_Byrack_Enable_IMM21_03 : 24|2@1+ (1,0) [0|3] ""  IMM
 SG_ M2I_Byrack_ReVeEnable_IMM21_03 : 26|2@1+ (1,0) [0|3] ""  IMM
 SG_ Reserved_03 : 28|4@1+ (1,0) [0|15] ""  IMM
 SG_ M2I_Byrack_IsPostTm_IMM21_03 : 32|8@1+ (0.01,0) [0|2.55] "s"  IMM
 SG_ M2I_Byrack_SysABStTm_IMM21_03 : 40|16@1+ (0.01,0) [0|655.35] "s"  IMM
 SG_ Reserved_03 : 56|8@1+ (1,0) [0|255] ""  IMM

BO_ 2332112276 M2I_Byrack_SUMDATA21__04: 8 MBMU
 SG_ CRC_M2I_Byrack_IMM21_04 : 0|8@1+ (1,0) [0|255] ""  IMM
 SG_ M2I_Byrack_HVS_IMM21_04 : 8|16@1+ (0.1,0) [0|6553.5] "v"  IMM
 SG_ M2I_Byrack_Enable_IMM21_04 : 24|2@1+ (1,0) [0|3] ""  IMM
 SG_ M2I_Byrack_ReVeEnable_IMM21_04 : 26|2@1+ (1,0) [0|3] ""  IMM
 SG_ Reserved_04 : 28|4@1+ (1,0) [0|15] ""  IMM
 SG_ M2I_Byrack_IsPostTm_IMM21_04 : 32|8@1+ (0.01,0) [0|2.55] "s"  IMM
 SG_ M2I_Byrack_SysABStTm_IMM21_04 : 40|16@1+ (0.01,0) [0|655.35] "s"  IMM
 SG_ Reserved_04 : 56|8@1+ (1,0) [0|255] ""  IMM

BO_ 2332112277 M2I_Byrack_SUMDATA21__05: 8 MBMU
 SG_ CRC_M2I_Byrack_IMM21_05 : 0|8@1+ (1,0) [0|255] ""  IMM
 SG_ M2I_Byrack_HVS_IMM21_05 : 8|16@1+ (0.1,0) [0|6553.5] "v"  IMM
 SG_ M2I_Byrack_Enable_IMM21_05 : 24|2@1+ (1,0) [0|3] ""  IMM
 SG_ M2I_Byrack_ReVeEnable_IMM21_05 : 26|2@1+ (1,0) [0|3] ""  IMM
 SG_ Reserved_05 : 28|4@1+ (1,0) [0|15] ""  IMM
 SG_ M2I_Byrack_IsPostTm_IMM21_05 : 32|8@1+ (0.01,0) [0|2.55] "s"  IMM
 SG_ M2I_Byrack_SysABStTm_IMM21_05 : 40|16@1+ (0.01,0) [0|655.35] "s"  IMM
 SG_ Reserved_05 : 56|8@1+ (1,0) [0|255] ""  IMM

BO_ 2332112278 M2I_Byrack_SUMDATA21__06: 8 MBMU
 SG_ CRC_M2I_Byrack_IMM21_06 : 0|8@1+ (1,0) [0|255] ""  IMM
 SG_ M2I_Byrack_HVS_IMM21_06 : 8|16@1+ (0.1,0) [0|6553.5] "v"  IMM
 SG_ M2I_Byrack_Enable_IMM21_06 : 24|2@1+ (1,0) [0|3] ""  IMM
 SG_ M2I_Byrack_ReVeEnable_IMM21_06 : 26|2@1+ (1,0) [0|3] ""  IMM
 SG_ Reserved_06 : 28|4@1+ (1,0) [0|15] ""  IMM
 SG_ M2I_Byrack_IsPostTm_IMM21_06 : 32|8@1+ (0.01,0) [0|2.55] "s"  IMM
 SG_ M2I_Byrack_SysABStTm_IMM21_06 : 40|16@1+ (0.01,0) [0|655.35] "s"  IMM
 SG_ Reserved_06 : 56|8@1+ (1,0) [0|255] ""  IMM

BO_ 2332112279 M2I_Byrack_SUMDATA21__07: 8 MBMU
 SG_ CRC_M2I_Byrack_IMM21_07 : 0|8@1+ (1,0) [0|255] ""  IMM
 SG_ M2I_Byrack_HVS_IMM21_07 : 8|16@1+ (0.1,0) [0|6553.5] "v"  IMM
 SG_ M2I_Byrack_Enable_IMM21_07 : 24|2@1+ (1,0) [0|3] ""  IMM
 SG_ M2I_Byrack_ReVeEnable_IMM21_07 : 26|2@1+ (1,0) [0|3] ""  IMM
 SG_ Reserved_07 : 28|4@1+ (1,0) [0|15] ""  IMM
 SG_ M2I_Byrack_IsPostTm_IMM21_07 : 32|8@1+ (0.01,0) [0|2.55] "s"  IMM
 SG_ M2I_Byrack_SysABStTm_IMM21_07 : 40|16@1+ (0.01,0) [0|655.35] "s"  IMM
 SG_ Reserved_07 : 56|8@1+ (1,0) [0|255] ""  IMM

BO_ 2332112280 M2I_Byrack_SUMDATA21__08: 8 MBMU
 SG_ CRC_M2I_Byrack_IMM21_08 : 0|8@1+ (1,0) [0|255] ""  IMM
 SG_ M2I_Byrack_HVS_IMM21_08 : 8|16@1+ (0.1,0) [0|6553.5] "v"  IMM
 SG_ M2I_Byrack_Enable_IMM21_08 : 24|2@1+ (1,0) [0|3] ""  IMM
 SG_ M2I_Byrack_ReVeEnable_IMM21_08 : 26|2@1+ (1,0) [0|3] ""  IMM
 SG_ Reserved_08 : 28|4@1+ (1,0) [0|15] ""  IMM
 SG_ M2I_Byrack_IsPostTm_IMM21_08 : 32|8@1+ (0.01,0) [0|2.55] "s"  IMM
 SG_ M2I_Byrack_SysABStTm_IMM21_08 : 40|16@1+ (0.01,0) [0|655.35] "s"  IMM
 SG_ Reserved_08 : 56|8@1+ (1,0) [0|255] ""  IMM

BO_ 2332112281 M2I_Byrack_SUMDATA21__09: 8 MBMU
 SG_ CRC_M2I_Byrack_IMM21_09 : 0|8@1+ (1,0) [0|255] ""  IMM
 SG_ M2I_Byrack_HVS_IMM21_09 : 8|16@1+ (0.1,0) [0|6553.5] "v"  IMM
 SG_ M2I_Byrack_Enable_IMM21_09 : 24|2@1+ (1,0) [0|3] ""  IMM
 SG_ M2I_Byrack_ReVeEnable_IMM21_09 : 26|2@1+ (1,0) [0|3] ""  IMM
 SG_ Reserved_09 : 28|4@1+ (1,0) [0|15] ""  IMM
 SG_ M2I_Byrack_IsPostTm_IMM21_09 : 32|8@1+ (0.01,0) [0|2.55] "s"  IMM
 SG_ M2I_Byrack_SysABStTm_IMM21_09 : 40|16@1+ (0.01,0) [0|655.35] "s"  IMM
 SG_ Reserved_09 : 56|8@1+ (1,0) [0|255] ""  IMM

BO_ 2332112282 M2I_Byrack_SUMDATA21__10: 8 MBMU
 SG_ CRC_M2I_Byrack_IMM21_10 : 0|8@1+ (1,0) [0|255] ""  IMM
 SG_ M2I_Byrack_HVS_IMM21_10 : 8|16@1+ (0.1,0) [0|6553.5] "v"  IMM
 SG_ M2I_Byrack_Enable_IMM21_10 : 24|2@1+ (1,0) [0|3] ""  IMM
 SG_ M2I_Byrack_ReVeEnable_IMM21_10 : 26|2@1+ (1,0) [0|3] ""  IMM
 SG_ Reserved_10 : 28|4@1+ (1,0) [0|15] ""  IMM
 SG_ M2I_Byrack_IsPostTm_IMM21_10 : 32|8@1+ (0.01,0) [0|2.55] "s"  IMM
 SG_ M2I_Byrack_SysABStTm_IMM21_10 : 40|16@1+ (0.01,0) [0|655.35] "s"  IMM
 SG_ Reserved_10 : 56|8@1+ (1,0) [0|255] ""  IMM

BO_ 2332112283 M2I_Byrack_SUMDATA21__11: 8 MBMU
 SG_ CRC_M2I_Byrack_IMM21_11 : 0|8@1+ (1,0) [0|255] ""  IMM
 SG_ M2I_Byrack_HVS_IMM21_11 : 8|16@1+ (0.1,0) [0|6553.5] "v"  IMM
 SG_ M2I_Byrack_Enable_IMM21_11 : 24|2@1+ (1,0) [0|3] ""  IMM
 SG_ M2I_Byrack_ReVeEnable_IMM21_11 : 26|2@1+ (1,0) [0|3] ""  IMM
 SG_ Reserved_11 : 28|4@1+ (1,0) [0|15] ""  IMM
 SG_ M2I_Byrack_IsPostTm_IMM21_11 : 32|8@1+ (0.01,0) [0|2.55] "s"  IMM
 SG_ M2I_Byrack_SysABStTm_IMM21_11 : 40|16@1+ (0.01,0) [0|655.35] "s"  IMM
 SG_ Reserved_11 : 56|8@1+ (1,0) [0|255] ""  IMM

BO_ 2332112284 M2I_Byrack_SUMDATA21__12: 8 MBMU
 SG_ CRC_M2I_Byrack_IMM21_12 : 0|8@1+ (1,0) [0|255] ""  IMM
 SG_ M2I_Byrack_HVS_IMM21_12 : 8|16@1+ (0.1,0) [0|6553.5] "v"  IMM
 SG_ M2I_Byrack_Enable_IMM21_12 : 24|2@1+ (1,0) [0|3] ""  IMM
 SG_ M2I_Byrack_ReVeEnable_IMM21_12 : 26|2@1+ (1,0) [0|3] ""  IMM
 SG_ Reserved_12 : 28|4@1+ (1,0) [0|15] ""  IMM
 SG_ M2I_Byrack_IsPostTm_IMM21_12 : 32|8@1+ (0.01,0) [0|2.55] "s"  IMM
 SG_ M2I_Byrack_SysABStTm_IMM21_12 : 40|16@1+ (0.01,0) [0|655.35] "s"  IMM
 SG_ Reserved_12 : 56|8@1+ (1,0) [0|255] ""  IMM

BO_ 2332112285 M2I_Byrack_SUMDATA21__13: 8 MBMU
 SG_ CRC_M2I_Byrack_IMM21_13 : 0|8@1+ (1,0) [0|255] ""  IMM
 SG_ M2I_Byrack_HVS_IMM21_13 : 8|16@1+ (0.1,0) [0|6553.5] "v"  IMM
 SG_ M2I_Byrack_Enable_IMM21_13 : 24|2@1+ (1,0) [0|3] ""  IMM
 SG_ M2I_Byrack_ReVeEnable_IMM21_13 : 26|2@1+ (1,0) [0|3] ""  IMM
 SG_ Reserved_13 : 28|4@1+ (1,0) [0|15] ""  IMM
 SG_ M2I_Byrack_IsPostTm_IMM21_13 : 32|8@1+ (0.01,0) [0|2.55] "s"  IMM
 SG_ M2I_Byrack_SysABStTm_IMM21_13 : 40|16@1+ (0.01,0) [0|655.35] "s"  IMM
 SG_ Reserved_13 : 56|8@1+ (1,0) [0|255] ""  IMM

BO_ 2332112286 M2I_Byrack_SUMDATA21__14: 8 MBMU
 SG_ CRC_M2I_Byrack_IMM21_14 : 0|8@1+ (1,0) [0|255] ""  IMM
 SG_ M2I_Byrack_HVS_IMM21_14 : 8|16@1+ (0.1,0) [0|6553.5] "v"  IMM
 SG_ M2I_Byrack_Enable_IMM21_14 : 24|2@1+ (1,0) [0|3] ""  IMM
 SG_ M2I_Byrack_ReVeEnable_IMM21_14 : 26|2@1+ (1,0) [0|3] ""  IMM
 SG_ Reserved_14 : 28|4@1+ (1,0) [0|15] ""  IMM
 SG_ M2I_Byrack_IsPostTm_IMM21_14 : 32|8@1+ (0.01,0) [0|2.55] "s"  IMM
 SG_ M2I_Byrack_SysABStTm_IMM21_14 : 40|16@1+ (0.01,0) [0|655.35] "s"  IMM
 SG_ Reserved_14 : 56|8@1+ (1,0) [0|255] ""  IMM

BO_ 2332112287 M2I_Byrack_SUMDATA21__15: 8 MBMU
 SG_ CRC_M2I_Byrack_IMM21_15 : 0|8@1+ (1,0) [0|255] ""  IMM
 SG_ M2I_Byrack_HVS_IMM21_15 : 8|16@1+ (0.1,0) [0|6553.5] "v"  IMM
 SG_ M2I_Byrack_Enable_IMM21_15 : 24|2@1+ (1,0) [0|3] ""  IMM
 SG_ M2I_Byrack_ReVeEnable_IMM21_15 : 26|2@1+ (1,0) [0|3] ""  IMM
 SG_ Reserved_15 : 28|4@1+ (1,0) [0|15] ""  IMM
 SG_ M2I_Byrack_IsPostTm_IMM21_15 : 32|8@1+ (0.01,0) [0|2.55] "s"  IMM
 SG_ M2I_Byrack_SysABStTm_IMM21_15 : 40|16@1+ (0.01,0) [0|655.35] "s"  IMM
 SG_ Reserved_15 : 56|8@1+ (1,0) [0|255] ""  IMM

BO_ 2332112288 M2I_Byrack_SUMDATA21__16: 8 MBMU
 SG_ CRC_M2I_Byrack_IMM21_16 : 0|8@1+ (1,0) [0|255] ""  IMM
 SG_ M2I_Byrack_HVS_IMM21_16 : 8|16@1+ (0.1,0) [0|6553.5] "v"  IMM
 SG_ M2I_Byrack_Enable_IMM21_16 : 24|2@1+ (1,0) [0|3] ""  IMM
 SG_ M2I_Byrack_ReVeEnable_IMM21_16 : 26|2@1+ (1,0) [0|3] ""  IMM
 SG_ Reserved_16 : 28|4@1+ (1,0) [0|15] ""  IMM
 SG_ M2I_Byrack_IsPostTm_IMM21_16 : 32|8@1+ (0.01,0) [0|2.55] "s"  IMM
 SG_ M2I_Byrack_SysABStTm_IMM21_16 : 40|16@1+ (0.01,0) [0|655.35] "s"  IMM
 SG_ Reserved_16 : 56|8@1+ (1,0) [0|255] ""  IMM

CM_ SG_ 2332110999 CRC_M2I_Byrack_IMM16_07 "CRC校验_IMM16";
CM_ SG_ 2332110999 M2I_Byrack_HVS_IMM16_07 "绝缘测量电压_IMM16";
CM_ SG_ 2332110999 M2I_Byrack_Enable_IMM16_07 "绝缘采样使能位_IMM16";
CM_ SG_ 2332110999 M2I_Byrack_ReVeEnable_IMM16_07 "读取软件版本使能位_IMM16";
CM_ SG_ 2332110999 Reserved_07 "预留预留";
CM_ SG_ 2332110999 M2I_Byrack_IsPostTm_IMM16_07 "绝缘采样时间_IMM16";
CM_ SG_ 2332110999 M2I_Byrack_SysABStTm_IMM16_07 "电压稳定时间_IMM16";
CM_ SG_ 2332111000 CRC_M2I_Byrack_IMM16_08 "CRC校验_IMM16";
CM_ SG_ 2332111000 M2I_Byrack_HVS_IMM16_08 "绝缘测量电压_IMM16";
CM_ SG_ 2332111000 M2I_Byrack_Enable_IMM16_08 "绝缘采样使能位_IMM16";
CM_ SG_ 2332111000 M2I_Byrack_ReVeEnable_IMM16_08 "读取软件版本使能位_IMM16";
CM_ SG_ 2332111000 Reserved_08 "预留预留";
CM_ SG_ 2332111000 M2I_Byrack_IsPostTm_IMM16_08 "绝缘采样时间_IMM16";
CM_ SG_ 2332111000 M2I_Byrack_SysABStTm_IMM16_08 "电压稳定时间_IMM16";
CM_ SG_ 2332111001 CRC_M2I_Byrack_IMM16_09 "CRC校验_IMM16";
CM_ SG_ 2332111001 M2I_Byrack_HVS_IMM16_09 "绝缘测量电压_IMM16";
CM_ SG_ 2332111001 M2I_Byrack_Enable_IMM16_09 "绝缘采样使能位_IMM16";
CM_ SG_ 2332111001 M2I_Byrack_ReVeEnable_IMM16_09 "读取软件版本使能位_IMM16";
CM_ SG_ 2332111001 Reserved_09 "预留预留";
CM_ SG_ 2332111001 M2I_Byrack_IsPostTm_IMM16_09 "绝缘采样时间_IMM16";
CM_ SG_ 2332111001 M2I_Byrack_SysABStTm_IMM16_09 "电压稳定时间_IMM16";
CM_ SG_ 2332111002 CRC_M2I_Byrack_IMM16_10 "CRC校验_IMM16";
CM_ SG_ 2332111002 M2I_Byrack_HVS_IMM16_10 "绝缘测量电压_IMM16";
CM_ SG_ 2332111002 M2I_Byrack_Enable_IMM16_10 "绝缘采样使能位_IMM16";
CM_ SG_ 2332111002 M2I_Byrack_ReVeEnable_IMM16_10 "读取软件版本使能位_IMM16";
CM_ SG_ 2332111002 Reserved_10 "预留预留";
CM_ SG_ 2332111002 M2I_Byrack_IsPostTm_IMM16_10 "绝缘采样时间_IMM16";
CM_ SG_ 2332111002 M2I_Byrack_SysABStTm_IMM16_10 "电压稳定时间_IMM16";
CM_ SG_ 2332111003 CRC_M2I_Byrack_IMM16_11 "CRC校验_IMM16";
CM_ SG_ 2332111003 M2I_Byrack_HVS_IMM16_11 "绝缘测量电压_IMM16";
CM_ SG_ 2332111003 M2I_Byrack_Enable_IMM16_11 "绝缘采样使能位_IMM16";
CM_ SG_ 2332111003 M2I_Byrack_ReVeEnable_IMM16_11 "读取软件版本使能位_IMM16";
CM_ SG_ 2332111003 Reserved_11 "预留预留";
CM_ SG_ 2332111003 M2I_Byrack_IsPostTm_IMM16_11 "绝缘采样时间_IMM16";
CM_ SG_ 2332111003 M2I_Byrack_SysABStTm_IMM16_11 "电压稳定时间_IMM16";
CM_ SG_ 2332111004 CRC_M2I_Byrack_IMM16_12 "CRC校验_IMM16";
CM_ SG_ 2332111004 M2I_Byrack_HVS_IMM16_12 "绝缘测量电压_IMM16";
CM_ SG_ 2332111004 M2I_Byrack_Enable_IMM16_12 "绝缘采样使能位_IMM16";
CM_ SG_ 2332111004 M2I_Byrack_ReVeEnable_IMM16_12 "读取软件版本使能位_IMM16";
CM_ SG_ 2332111004 Reserved_12 "预留预留";
CM_ SG_ 2332111004 M2I_Byrack_IsPostTm_IMM16_12 "绝缘采样时间_IMM16";
CM_ SG_ 2332111004 M2I_Byrack_SysABStTm_IMM16_12 "电压稳定时间_IMM16";
CM_ SG_ 2332111005 CRC_M2I_Byrack_IMM16_13 "CRC校验_IMM16";
CM_ SG_ 2332111005 M2I_Byrack_HVS_IMM16_13 "绝缘测量电压_IMM16";
CM_ SG_ 2332111005 M2I_Byrack_Enable_IMM16_13 "绝缘采样使能位_IMM16";
CM_ SG_ 2332111005 M2I_Byrack_ReVeEnable_IMM16_13 "读取软件版本使能位_IMM16";
CM_ SG_ 2332111005 Reserved_13 "预留预留";
CM_ SG_ 2332111005 M2I_Byrack_IsPostTm_IMM16_13 "绝缘采样时间_IMM16";
CM_ SG_ 2332111005 M2I_Byrack_SysABStTm_IMM16_13 "电压稳定时间_IMM16";
CM_ SG_ 2332111006 CRC_M2I_Byrack_IMM16_14 "CRC校验_IMM16";
CM_ SG_ 2332111006 M2I_Byrack_HVS_IMM16_14 "绝缘测量电压_IMM16";
CM_ SG_ 2332111006 M2I_Byrack_Enable_IMM16_14 "绝缘采样使能位_IMM16";
CM_ SG_ 2332111006 M2I_Byrack_ReVeEnable_IMM16_14 "读取软件版本使能位_IMM16";
CM_ SG_ 2332111006 Reserved_14 "预留预留";
CM_ SG_ 2332111006 M2I_Byrack_IsPostTm_IMM16_14 "绝缘采样时间_IMM16";
CM_ SG_ 2332111006 M2I_Byrack_SysABStTm_IMM16_14 "电压稳定时间_IMM16";
CM_ SG_ 2332111007 CRC_M2I_Byrack_IMM16_15 "CRC校验_IMM16";
CM_ SG_ 2332111007 M2I_Byrack_HVS_IMM16_15 "绝缘测量电压_IMM16";
CM_ SG_ 2332111007 M2I_Byrack_Enable_IMM16_15 "绝缘采样使能位_IMM16";
CM_ SG_ 2332111007 M2I_Byrack_ReVeEnable_IMM16_15 "读取软件版本使能位_IMM16";
CM_ SG_ 2332111007 Reserved_15 "预留预留";
CM_ SG_ 2332111007 M2I_Byrack_IsPostTm_IMM16_15 "绝缘采样时间_IMM16";
CM_ SG_ 2332111007 M2I_Byrack_SysABStTm_IMM16_15 "电压稳定时间_IMM16";
CM_ SG_ 2332111008 CRC_M2I_Byrack_IMM16_16 "CRC校验_IMM16";
CM_ SG_ 2332111008 M2I_Byrack_HVS_IMM16_16 "绝缘测量电压_IMM16";
CM_ SG_ 2332111008 M2I_Byrack_Enable_IMM16_16 "绝缘采样使能位_IMM16";
CM_ SG_ 2332111008 M2I_Byrack_ReVeEnable_IMM16_16 "读取软件版本使能位_IMM16";
CM_ SG_ 2332111008 Reserved_16 "预留预留";
CM_ SG_ 2332111008 M2I_Byrack_IsPostTm_IMM16_16 "绝缘采样时间_IMM16";
CM_ SG_ 2332111008 M2I_Byrack_SysABStTm_IMM16_16 "电压稳定时间_IMM16";
CM_ SG_ 2332111009 CRC_M2I_Byrack_IMM16_17 "CRC校验_IMM16";
CM_ SG_ 2332111009 M2I_Byrack_HVS_IMM16_17 "绝缘测量电压_IMM16";
CM_ SG_ 2332111009 M2I_Byrack_Enable_IMM16_17 "绝缘采样使能位_IMM16";
CM_ SG_ 2332111009 M2I_Byrack_ReVeEnable_IMM16_17 "读取软件版本使能位_IMM16";
CM_ SG_ 2332111009 Reserved_17 "预留预留";
CM_ SG_ 2332111009 M2I_Byrack_IsPostTm_IMM16_17 "绝缘采样时间_IMM16";
CM_ SG_ 2332111009 M2I_Byrack_SysABStTm_IMM16_17 "电压稳定时间_IMM16";
CM_ SG_ 2332111010 CRC_M2I_Byrack_IMM16_18 "CRC校验_IMM16";
CM_ SG_ 2332111010 M2I_Byrack_HVS_IMM16_18 "绝缘测量电压_IMM16";
CM_ SG_ 2332111010 M2I_Byrack_Enable_IMM16_18 "绝缘采样使能位_IMM16";
CM_ SG_ 2332111010 M2I_Byrack_ReVeEnable_IMM16_18 "读取软件版本使能位_IMM16";
CM_ SG_ 2332111010 Reserved_18 "预留预留";
CM_ SG_ 2332111010 M2I_Byrack_IsPostTm_IMM16_18 "绝缘采样时间_IMM16";
CM_ SG_ 2332111010 M2I_Byrack_SysABStTm_IMM16_18 "电压稳定时间_IMM16";
CM_ SG_ 2332111011 CRC_M2I_Byrack_IMM16_19 "CRC校验_IMM16";
CM_ SG_ 2332111011 M2I_Byrack_HVS_IMM16_19 "绝缘测量电压_IMM16";
CM_ SG_ 2332111011 M2I_Byrack_Enable_IMM16_19 "绝缘采样使能位_IMM16";
CM_ SG_ 2332111011 M2I_Byrack_ReVeEnable_IMM16_19 "读取软件版本使能位_IMM16";
CM_ SG_ 2332111011 Reserved_19 "预留预留";
CM_ SG_ 2332111011 M2I_Byrack_IsPostTm_IMM16_19 "绝缘采样时间_IMM16";
CM_ SG_ 2332111011 M2I_Byrack_SysABStTm_IMM16_19 "电压稳定时间_IMM16";
CM_ SG_ 2332111012 CRC_M2I_Byrack_IMM16_20 "CRC校验_IMM16";
CM_ SG_ 2332111012 M2I_Byrack_HVS_IMM16_20 "绝缘测量电压_IMM16";
CM_ SG_ 2332111012 M2I_Byrack_Enable_IMM16_20 "绝缘采样使能位_IMM16";
CM_ SG_ 2332111012 M2I_Byrack_ReVeEnable_IMM16_20 "读取软件版本使能位_IMM16";
CM_ SG_ 2332111012 Reserved_20 "预留预留";
CM_ SG_ 2332111012 M2I_Byrack_IsPostTm_IMM16_20 "绝缘采样时间_IMM16";
CM_ SG_ 2332111012 M2I_Byrack_SysABStTm_IMM16_20 "电压稳定时间_IMM16";
CM_ SG_ 2332111013 CRC_M2I_Byrack_IMM16_21 "CRC校验_IMM16";
CM_ SG_ 2332111013 M2I_Byrack_HVS_IMM16_21 "绝缘测量电压_IMM16";
CM_ SG_ 2332111013 M2I_Byrack_Enable_IMM16_21 "绝缘采样使能位_IMM16";
CM_ SG_ 2332111013 M2I_Byrack_ReVeEnable_IMM16_21 "读取软件版本使能位_IMM16";
CM_ SG_ 2332111013 Reserved_21 "预留预留";
CM_ SG_ 2332111013 M2I_Byrack_IsPostTm_IMM16_21 "绝缘采样时间_IMM16";
CM_ SG_ 2332111013 M2I_Byrack_SysABStTm_IMM16_21 "电压稳定时间_IMM16";
CM_ SG_ 2332111014 CRC_M2I_Byrack_IMM16_22 "CRC校验_IMM16";
CM_ SG_ 2332111014 M2I_Byrack_HVS_IMM16_22 "绝缘测量电压_IMM16";
CM_ SG_ 2332111014 M2I_Byrack_Enable_IMM16_22 "绝缘采样使能位_IMM16";
CM_ SG_ 2332111014 M2I_Byrack_ReVeEnable_IMM16_22 "读取软件版本使能位_IMM16";
CM_ SG_ 2332111014 Reserved_22 "预留预留";
CM_ SG_ 2332111014 M2I_Byrack_IsPostTm_IMM16_22 "绝缘采样时间_IMM16";
CM_ SG_ 2332111014 M2I_Byrack_SysABStTm_IMM16_22 "电压稳定时间_IMM16";
CM_ SG_ 2332111015 CRC_M2I_Byrack_IMM16_23 "CRC校验_IMM16";
CM_ SG_ 2332111015 M2I_Byrack_HVS_IMM16_23 "绝缘测量电压_IMM16";
CM_ SG_ 2332111015 M2I_Byrack_Enable_IMM16_23 "绝缘采样使能位_IMM16";
CM_ SG_ 2332111015 M2I_Byrack_ReVeEnable_IMM16_23 "读取软件版本使能位_IMM16";
CM_ SG_ 2332111015 Reserved_23 "预留预留";
CM_ SG_ 2332111015 M2I_Byrack_IsPostTm_IMM16_23 "绝缘采样时间_IMM16";
CM_ SG_ 2332111015 M2I_Byrack_SysABStTm_IMM16_23 "电压稳定时间_IMM16";
CM_ SG_ 2332111016 CRC_M2I_Byrack_IMM16_24 "CRC校验_IMM16";
CM_ SG_ 2332111016 M2I_Byrack_HVS_IMM16_24 "绝缘测量电压_IMM16";
CM_ SG_ 2332111016 M2I_Byrack_Enable_IMM16_24 "绝缘采样使能位_IMM16";
CM_ SG_ 2332111016 M2I_Byrack_ReVeEnable_IMM16_24 "读取软件版本使能位_IMM16";
CM_ SG_ 2332111016 Reserved_24 "预留预留";
CM_ SG_ 2332111016 M2I_Byrack_IsPostTm_IMM16_24 "绝缘采样时间_IMM16";
CM_ SG_ 2332111016 M2I_Byrack_SysABStTm_IMM16_24 "电压稳定时间_IMM16";
CM_ SG_ 2332111017 CRC_M2I_Byrack_IMM16_25 "CRC校验_IMM16";
CM_ SG_ 2332111017 M2I_Byrack_HVS_IMM16_25 "绝缘测量电压_IMM16";
CM_ SG_ 2332111017 M2I_Byrack_Enable_IMM16_25 "绝缘采样使能位_IMM16";
CM_ SG_ 2332111017 M2I_Byrack_ReVeEnable_IMM16_25 "读取软件版本使能位_IMM16";
CM_ SG_ 2332111017 Reserved_25 "预留预留";
CM_ SG_ 2332111017 M2I_Byrack_IsPostTm_IMM16_25 "绝缘采样时间_IMM16";
CM_ SG_ 2332111017 M2I_Byrack_SysABStTm_IMM16_25 "电压稳定时间_IMM16";
CM_ SG_ 2332111018 CRC_M2I_Byrack_IMM16_26 "CRC校验_IMM16";
CM_ SG_ 2332111018 M2I_Byrack_HVS_IMM16_26 "绝缘测量电压_IMM16";
CM_ SG_ 2332111018 M2I_Byrack_Enable_IMM16_26 "绝缘采样使能位_IMM16";
CM_ SG_ 2332111018 M2I_Byrack_ReVeEnable_IMM16_26 "读取软件版本使能位_IMM16";
CM_ SG_ 2332111018 Reserved_26 "预留预留";
CM_ SG_ 2332111018 M2I_Byrack_IsPostTm_IMM16_26 "绝缘采样时间_IMM16";
CM_ SG_ 2332111018 M2I_Byrack_SysABStTm_IMM16_26 "电压稳定时间_IMM16";
CM_ SG_ 2332111019 CRC_M2I_Byrack_IMM16_27 "CRC校验_IMM16";
CM_ SG_ 2332111019 M2I_Byrack_HVS_IMM16_27 "绝缘测量电压_IMM16";
CM_ SG_ 2332111019 M2I_Byrack_Enable_IMM16_27 "绝缘采样使能位_IMM16";
CM_ SG_ 2332111019 M2I_Byrack_ReVeEnable_IMM16_27 "读取软件版本使能位_IMM16";
CM_ SG_ 2332111019 Reserved_27 "预留预留";
CM_ SG_ 2332111019 M2I_Byrack_IsPostTm_IMM16_27 "绝缘采样时间_IMM16";
CM_ SG_ 2332111019 M2I_Byrack_SysABStTm_IMM16_27 "电压稳定时间_IMM16";
CM_ SG_ 2332111020 CRC_M2I_Byrack_IMM16_28 "CRC校验_IMM16";
CM_ SG_ 2332111020 M2I_Byrack_HVS_IMM16_28 "绝缘测量电压_IMM16";
CM_ SG_ 2332111020 M2I_Byrack_Enable_IMM16_28 "绝缘采样使能位_IMM16";
CM_ SG_ 2332111020 M2I_Byrack_ReVeEnable_IMM16_28 "读取软件版本使能位_IMM16";
CM_ SG_ 2332111020 Reserved_28 "预留预留";
CM_ SG_ 2332111020 M2I_Byrack_IsPostTm_IMM16_28 "绝缘采样时间_IMM16";
CM_ SG_ 2332111020 M2I_Byrack_SysABStTm_IMM16_28 "电压稳定时间_IMM16";
CM_ SG_ 2332111021 CRC_M2I_Byrack_IMM16_29 "CRC校验_IMM16";
CM_ SG_ 2332111021 M2I_Byrack_HVS_IMM16_29 "绝缘测量电压_IMM16";
CM_ SG_ 2332111021 M2I_Byrack_Enable_IMM16_29 "绝缘采样使能位_IMM16";
CM_ SG_ 2332111021 M2I_Byrack_ReVeEnable_IMM16_29 "读取软件版本使能位_IMM16";
CM_ SG_ 2332111021 Reserved_29 "预留预留";
CM_ SG_ 2332111021 M2I_Byrack_IsPostTm_IMM16_29 "绝缘采样时间_IMM16";
CM_ SG_ 2332111021 M2I_Byrack_SysABStTm_IMM16_29 "电压稳定时间_IMM16";
CM_ SG_ 2332111022 CRC_M2I_Byrack_IMM16_30 "CRC校验_IMM16";
CM_ SG_ 2332111022 M2I_Byrack_HVS_IMM16_30 "绝缘测量电压_IMM16";
CM_ SG_ 2332111022 M2I_Byrack_Enable_IMM16_30 "绝缘采样使能位_IMM16";
CM_ SG_ 2332111022 M2I_Byrack_ReVeEnable_IMM16_30 "读取软件版本使能位_IMM16";
CM_ SG_ 2332111022 Reserved_30 "预留预留";
CM_ SG_ 2332111022 M2I_Byrack_IsPostTm_IMM16_30 "绝缘采样时间_IMM16";
CM_ SG_ 2332111022 M2I_Byrack_SysABStTm_IMM16_30 "电压稳定时间_IMM16";
CM_ SG_ 2332111023 CRC_M2I_Byrack_IMM16_31 "CRC校验_IMM16";
CM_ SG_ 2332111023 M2I_Byrack_HVS_IMM16_31 "绝缘测量电压_IMM16";
CM_ SG_ 2332111023 M2I_Byrack_Enable_IMM16_31 "绝缘采样使能位_IMM16";
CM_ SG_ 2332111023 M2I_Byrack_ReVeEnable_IMM16_31 "读取软件版本使能位_IMM16";
CM_ SG_ 2332111023 Reserved_31 "预留预留";
CM_ SG_ 2332111023 M2I_Byrack_IsPostTm_IMM16_31 "绝缘采样时间_IMM16";
CM_ SG_ 2332111023 M2I_Byrack_SysABStTm_IMM16_31 "电压稳定时间_IMM16";
CM_ SG_ 2332111249 CRC_M2I_Byrack_IMM17_01 "CRC校验_IMM17";
CM_ SG_ 2332111249 M2I_Byrack_HVS_IMM17_01 "绝缘测量电压_IMM17";
CM_ SG_ 2332111249 M2I_Byrack_Enable_IMM17_01 "绝缘采样使能位_IMM17";
CM_ SG_ 2332111249 M2I_Byrack_ReVeEnable_IMM17_01 "读取软件版本使能位_IMM17";
CM_ SG_ 2332111249 Reserved_01 "预留预留";
CM_ SG_ 2332111249 M2I_Byrack_IsPostTm_IMM17_01 "绝缘采样时间_IMM17";
CM_ SG_ 2332111249 M2I_Byrack_SysABStTm_IMM17_01 "电压稳定时间_IMM17";
CM_ SG_ 2332111250 CRC_M2I_Byrack_IMM17_02 "CRC校验_IMM17";
CM_ SG_ 2332111250 M2I_Byrack_HVS_IMM17_02 "绝缘测量电压_IMM17";
CM_ SG_ 2332111250 M2I_Byrack_Enable_IMM17_02 "绝缘采样使能位_IMM17";
CM_ SG_ 2332111250 M2I_Byrack_ReVeEnable_IMM17_02 "读取软件版本使能位_IMM17";
CM_ SG_ 2332111250 Reserved_02 "预留预留";
CM_ SG_ 2332111250 M2I_Byrack_IsPostTm_IMM17_02 "绝缘采样时间_IMM17";
CM_ SG_ 2332111250 M2I_Byrack_SysABStTm_IMM17_02 "电压稳定时间_IMM17";
CM_ SG_ 2332111251 CRC_M2I_Byrack_IMM17_03 "CRC校验_IMM17";
CM_ SG_ 2332111251 M2I_Byrack_HVS_IMM17_03 "绝缘测量电压_IMM17";
CM_ SG_ 2332111251 M2I_Byrack_Enable_IMM17_03 "绝缘采样使能位_IMM17";
CM_ SG_ 2332111251 M2I_Byrack_ReVeEnable_IMM17_03 "读取软件版本使能位_IMM17";
CM_ SG_ 2332111251 Reserved_03 "预留预留";
CM_ SG_ 2332111251 M2I_Byrack_IsPostTm_IMM17_03 "绝缘采样时间_IMM17";
CM_ SG_ 2332111251 M2I_Byrack_SysABStTm_IMM17_03 "电压稳定时间_IMM17";
CM_ SG_ 2332111252 CRC_M2I_Byrack_IMM17_04 "CRC校验_IMM17";
CM_ SG_ 2332111252 M2I_Byrack_HVS_IMM17_04 "绝缘测量电压_IMM17";
CM_ SG_ 2332111252 M2I_Byrack_Enable_IMM17_04 "绝缘采样使能位_IMM17";
CM_ SG_ 2332111252 M2I_Byrack_ReVeEnable_IMM17_04 "读取软件版本使能位_IMM17";
CM_ SG_ 2332111252 Reserved_04 "预留预留";
CM_ SG_ 2332111252 M2I_Byrack_IsPostTm_IMM17_04 "绝缘采样时间_IMM17";
CM_ SG_ 2332111252 M2I_Byrack_SysABStTm_IMM17_04 "电压稳定时间_IMM17";
CM_ SG_ 2332111253 CRC_M2I_Byrack_IMM17_05 "CRC校验_IMM17";
CM_ SG_ 2332111253 M2I_Byrack_HVS_IMM17_05 "绝缘测量电压_IMM17";
CM_ SG_ 2332111253 M2I_Byrack_Enable_IMM17_05 "绝缘采样使能位_IMM17";
CM_ SG_ 2332111253 M2I_Byrack_ReVeEnable_IMM17_05 "读取软件版本使能位_IMM17";
CM_ SG_ 2332111253 Reserved_05 "预留预留";
CM_ SG_ 2332111253 M2I_Byrack_IsPostTm_IMM17_05 "绝缘采样时间_IMM17";
CM_ SG_ 2332111253 M2I_Byrack_SysABStTm_IMM17_05 "电压稳定时间_IMM17";
CM_ SG_ 2332111254 CRC_M2I_Byrack_IMM17_06 "CRC校验_IMM17";
CM_ SG_ 2332111254 M2I_Byrack_HVS_IMM17_06 "绝缘测量电压_IMM17";
CM_ SG_ 2332111254 M2I_Byrack_Enable_IMM17_06 "绝缘采样使能位_IMM17";
CM_ SG_ 2332111254 M2I_Byrack_ReVeEnable_IMM17_06 "读取软件版本使能位_IMM17";
CM_ SG_ 2332111254 Reserved_06 "预留预留";
CM_ SG_ 2332111254 M2I_Byrack_IsPostTm_IMM17_06 "绝缘采样时间_IMM17";
CM_ SG_ 2332111254 M2I_Byrack_SysABStTm_IMM17_06 "电压稳定时间_IMM17";
CM_ SG_ 2332111255 CRC_M2I_Byrack_IMM17_07 "CRC校验_IMM17";
CM_ SG_ 2332111255 M2I_Byrack_HVS_IMM17_07 "绝缘测量电压_IMM17";
CM_ SG_ 2332111255 M2I_Byrack_Enable_IMM17_07 "绝缘采样使能位_IMM17";
CM_ SG_ 2332111255 M2I_Byrack_ReVeEnable_IMM17_07 "读取软件版本使能位_IMM17";
CM_ SG_ 2332111255 Reserved_07 "预留预留";
CM_ SG_ 2332111255 M2I_Byrack_IsPostTm_IMM17_07 "绝缘采样时间_IMM17";
CM_ SG_ 2332111255 M2I_Byrack_SysABStTm_IMM17_07 "电压稳定时间_IMM17";
CM_ SG_ 2332111256 CRC_M2I_Byrack_IMM17_08 "CRC校验_IMM17";
CM_ SG_ 2332111256 M2I_Byrack_HVS_IMM17_08 "绝缘测量电压_IMM17";
CM_ SG_ 2332111256 M2I_Byrack_Enable_IMM17_08 "绝缘采样使能位_IMM17";
CM_ SG_ 2332111256 M2I_Byrack_ReVeEnable_IMM17_08 "读取软件版本使能位_IMM17";
CM_ SG_ 2332111256 Reserved_08 "预留预留";
CM_ SG_ 2332111256 M2I_Byrack_IsPostTm_IMM17_08 "绝缘采样时间_IMM17";
CM_ SG_ 2332111256 M2I_Byrack_SysABStTm_IMM17_08 "电压稳定时间_IMM17";
CM_ SG_ 2332111257 CRC_M2I_Byrack_IMM17_09 "CRC校验_IMM17";
CM_ SG_ 2332111257 M2I_Byrack_HVS_IMM17_09 "绝缘测量电压_IMM17";
CM_ SG_ 2332111257 M2I_Byrack_Enable_IMM17_09 "绝缘采样使能位_IMM17";
CM_ SG_ 2332111257 M2I_Byrack_ReVeEnable_IMM17_09 "读取软件版本使能位_IMM17";
CM_ SG_ 2332111257 Reserved_09 "预留预留";
CM_ SG_ 2332111257 M2I_Byrack_IsPostTm_IMM17_09 "绝缘采样时间_IMM17";
CM_ SG_ 2332111257 M2I_Byrack_SysABStTm_IMM17_09 "电压稳定时间_IMM17";
CM_ SG_ 2332111258 CRC_M2I_Byrack_IMM17_10 "CRC校验_IMM17";
CM_ SG_ 2332111258 M2I_Byrack_HVS_IMM17_10 "绝缘测量电压_IMM17";
CM_ SG_ 2332111258 M2I_Byrack_Enable_IMM17_10 "绝缘采样使能位_IMM17";
CM_ SG_ 2332111258 M2I_Byrack_ReVeEnable_IMM17_10 "读取软件版本使能位_IMM17";
CM_ SG_ 2332111258 Reserved_10 "预留预留";
CM_ SG_ 2332111258 M2I_Byrack_IsPostTm_IMM17_10 "绝缘采样时间_IMM17";
CM_ SG_ 2332111258 M2I_Byrack_SysABStTm_IMM17_10 "电压稳定时间_IMM17";
CM_ SG_ 2332111259 CRC_M2I_Byrack_IMM17_11 "CRC校验_IMM17";
CM_ SG_ 2332111259 M2I_Byrack_HVS_IMM17_11 "绝缘测量电压_IMM17";
CM_ SG_ 2332111259 M2I_Byrack_Enable_IMM17_11 "绝缘采样使能位_IMM17";
CM_ SG_ 2332111259 M2I_Byrack_ReVeEnable_IMM17_11 "读取软件版本使能位_IMM17";
CM_ SG_ 2332111259 Reserved_11 "预留预留";
CM_ SG_ 2332111259 M2I_Byrack_IsPostTm_IMM17_11 "绝缘采样时间_IMM17";
CM_ SG_ 2332111259 M2I_Byrack_SysABStTm_IMM17_11 "电压稳定时间_IMM17";
CM_ SG_ 2332111260 CRC_M2I_Byrack_IMM17_12 "CRC校验_IMM17";
CM_ SG_ 2332111260 M2I_Byrack_HVS_IMM17_12 "绝缘测量电压_IMM17";
CM_ SG_ 2332111260 M2I_Byrack_Enable_IMM17_12 "绝缘采样使能位_IMM17";
CM_ SG_ 2332111260 M2I_Byrack_ReVeEnable_IMM17_12 "读取软件版本使能位_IMM17";
CM_ SG_ 2332111260 Reserved_12 "预留预留";
CM_ SG_ 2332111260 M2I_Byrack_IsPostTm_IMM17_12 "绝缘采样时间_IMM17";
CM_ SG_ 2332111260 M2I_Byrack_SysABStTm_IMM17_12 "电压稳定时间_IMM17";
CM_ SG_ 2332111261 CRC_M2I_Byrack_IMM17_13 "CRC校验_IMM17";
CM_ SG_ 2332111261 M2I_Byrack_HVS_IMM17_13 "绝缘测量电压_IMM17";
CM_ SG_ 2332111261 M2I_Byrack_Enable_IMM17_13 "绝缘采样使能位_IMM17";
CM_ SG_ 2332111261 M2I_Byrack_ReVeEnable_IMM17_13 "读取软件版本使能位_IMM17";
CM_ SG_ 2332111261 Reserved_13 "预留预留";
CM_ SG_ 2332111261 M2I_Byrack_IsPostTm_IMM17_13 "绝缘采样时间_IMM17";
CM_ SG_ 2332111261 M2I_Byrack_SysABStTm_IMM17_13 "电压稳定时间_IMM17";
CM_ SG_ 2332111262 CRC_M2I_Byrack_IMM17_14 "CRC校验_IMM17";
CM_ SG_ 2332111262 M2I_Byrack_HVS_IMM17_14 "绝缘测量电压_IMM17";
CM_ SG_ 2332111262 M2I_Byrack_Enable_IMM17_14 "绝缘采样使能位_IMM17";
CM_ SG_ 2332111262 M2I_Byrack_ReVeEnable_IMM17_14 "读取软件版本使能位_IMM17";
CM_ SG_ 2332111262 Reserved_14 "预留预留";
CM_ SG_ 2332111262 M2I_Byrack_IsPostTm_IMM17_14 "绝缘采样时间_IMM17";
CM_ SG_ 2332111262 M2I_Byrack_SysABStTm_IMM17_14 "电压稳定时间_IMM17";
CM_ SG_ 2332111263 CRC_M2I_Byrack_IMM17_15 "CRC校验_IMM17";
CM_ SG_ 2332111263 M2I_Byrack_HVS_IMM17_15 "绝缘测量电压_IMM17";
CM_ SG_ 2332111263 M2I_Byrack_Enable_IMM17_15 "绝缘采样使能位_IMM17";
CM_ SG_ 2332111263 M2I_Byrack_ReVeEnable_IMM17_15 "读取软件版本使能位_IMM17";
CM_ SG_ 2332111263 Reserved_15 "预留预留";
CM_ SG_ 2332111263 M2I_Byrack_IsPostTm_IMM17_15 "绝缘采样时间_IMM17";
CM_ SG_ 2332111263 M2I_Byrack_SysABStTm_IMM17_15 "电压稳定时间_IMM17";
CM_ SG_ 2332111264 CRC_M2I_Byrack_IMM17_16 "CRC校验_IMM17";
CM_ SG_ 2332111264 M2I_Byrack_HVS_IMM17_16 "绝缘测量电压_IMM17";
CM_ SG_ 2332111264 M2I_Byrack_Enable_IMM17_16 "绝缘采样使能位_IMM17";
CM_ SG_ 2332111264 M2I_Byrack_ReVeEnable_IMM17_16 "读取软件版本使能位_IMM17";
CM_ SG_ 2332111264 Reserved_16 "预留预留";
CM_ SG_ 2332111264 M2I_Byrack_IsPostTm_IMM17_16 "绝缘采样时间_IMM17";
CM_ SG_ 2332111264 M2I_Byrack_SysABStTm_IMM17_16 "电压稳定时间_IMM17";
CM_ SG_ 2332111265 CRC_M2I_Byrack_IMM17_17 "CRC校验_IMM17";
CM_ SG_ 2332111265 M2I_Byrack_HVS_IMM17_17 "绝缘测量电压_IMM17";
CM_ SG_ 2332111265 M2I_Byrack_Enable_IMM17_17 "绝缘采样使能位_IMM17";
CM_ SG_ 2332111265 M2I_Byrack_ReVeEnable_IMM17_17 "读取软件版本使能位_IMM17";
CM_ SG_ 2332111265 Reserved_17 "预留预留";
CM_ SG_ 2332111265 M2I_Byrack_IsPostTm_IMM17_17 "绝缘采样时间_IMM17";
CM_ SG_ 2332111265 M2I_Byrack_SysABStTm_IMM17_17 "电压稳定时间_IMM17";
CM_ SG_ 2332111266 CRC_M2I_Byrack_IMM17_18 "CRC校验_IMM17";
CM_ SG_ 2332111266 M2I_Byrack_HVS_IMM17_18 "绝缘测量电压_IMM17";
CM_ SG_ 2332111266 M2I_Byrack_Enable_IMM17_18 "绝缘采样使能位_IMM17";
CM_ SG_ 2332111266 M2I_Byrack_ReVeEnable_IMM17_18 "读取软件版本使能位_IMM17";
CM_ SG_ 2332111266 Reserved_18 "预留预留";
CM_ SG_ 2332111266 M2I_Byrack_IsPostTm_IMM17_18 "绝缘采样时间_IMM17";
CM_ SG_ 2332111266 M2I_Byrack_SysABStTm_IMM17_18 "电压稳定时间_IMM17";
CM_ SG_ 2332111267 CRC_M2I_Byrack_IMM17_19 "CRC校验_IMM17";
CM_ SG_ 2332111267 M2I_Byrack_HVS_IMM17_19 "绝缘测量电压_IMM17";
CM_ SG_ 2332111267 M2I_Byrack_Enable_IMM17_19 "绝缘采样使能位_IMM17";
CM_ SG_ 2332111267 M2I_Byrack_ReVeEnable_IMM17_19 "读取软件版本使能位_IMM17";
CM_ SG_ 2332111267 Reserved_19 "预留预留";
CM_ SG_ 2332111267 M2I_Byrack_IsPostTm_IMM17_19 "绝缘采样时间_IMM17";
CM_ SG_ 2332111267 M2I_Byrack_SysABStTm_IMM17_19 "电压稳定时间_IMM17";
CM_ SG_ 2332111268 CRC_M2I_Byrack_IMM17_20 "CRC校验_IMM17";
CM_ SG_ 2332111268 M2I_Byrack_HVS_IMM17_20 "绝缘测量电压_IMM17";
CM_ SG_ 2332111268 M2I_Byrack_Enable_IMM17_20 "绝缘采样使能位_IMM17";
CM_ SG_ 2332111268 M2I_Byrack_ReVeEnable_IMM17_20 "读取软件版本使能位_IMM17";
CM_ SG_ 2332111268 Reserved_20 "预留预留";
CM_ SG_ 2332111268 M2I_Byrack_IsPostTm_IMM17_20 "绝缘采样时间_IMM17";
CM_ SG_ 2332111268 M2I_Byrack_SysABStTm_IMM17_20 "电压稳定时间_IMM17";
CM_ SG_ 2332111269 CRC_M2I_Byrack_IMM17_21 "CRC校验_IMM17";
CM_ SG_ 2332111269 M2I_Byrack_HVS_IMM17_21 "绝缘测量电压_IMM17";
CM_ SG_ 2332111269 M2I_Byrack_Enable_IMM17_21 "绝缘采样使能位_IMM17";
CM_ SG_ 2332111269 M2I_Byrack_ReVeEnable_IMM17_21 "读取软件版本使能位_IMM17";
CM_ SG_ 2332111269 Reserved_21 "预留预留";
CM_ SG_ 2332111269 M2I_Byrack_IsPostTm_IMM17_21 "绝缘采样时间_IMM17";
CM_ SG_ 2332111269 M2I_Byrack_SysABStTm_IMM17_21 "电压稳定时间_IMM17";
CM_ SG_ 2332111270 CRC_M2I_Byrack_IMM17_22 "CRC校验_IMM17";
CM_ SG_ 2332111270 M2I_Byrack_HVS_IMM17_22 "绝缘测量电压_IMM17";
CM_ SG_ 2332111270 M2I_Byrack_Enable_IMM17_22 "绝缘采样使能位_IMM17";
CM_ SG_ 2332111270 M2I_Byrack_ReVeEnable_IMM17_22 "读取软件版本使能位_IMM17";
CM_ SG_ 2332111270 Reserved_22 "预留预留";
CM_ SG_ 2332111270 M2I_Byrack_IsPostTm_IMM17_22 "绝缘采样时间_IMM17";
CM_ SG_ 2332111270 M2I_Byrack_SysABStTm_IMM17_22 "电压稳定时间_IMM17";
CM_ SG_ 2332111271 CRC_M2I_Byrack_IMM17_23 "CRC校验_IMM17";
CM_ SG_ 2332111271 M2I_Byrack_HVS_IMM17_23 "绝缘测量电压_IMM17";
CM_ SG_ 2332111271 M2I_Byrack_Enable_IMM17_23 "绝缘采样使能位_IMM17";
CM_ SG_ 2332111271 M2I_Byrack_ReVeEnable_IMM17_23 "读取软件版本使能位_IMM17";
CM_ SG_ 2332111271 Reserved_23 "预留预留";
CM_ SG_ 2332111271 M2I_Byrack_IsPostTm_IMM17_23 "绝缘采样时间_IMM17";
CM_ SG_ 2332111271 M2I_Byrack_SysABStTm_IMM17_23 "电压稳定时间_IMM17";
CM_ SG_ 2332111272 CRC_M2I_Byrack_IMM17_24 "CRC校验_IMM17";
CM_ SG_ 2332111272 M2I_Byrack_HVS_IMM17_24 "绝缘测量电压_IMM17";
CM_ SG_ 2332111272 M2I_Byrack_Enable_IMM17_24 "绝缘采样使能位_IMM17";
CM_ SG_ 2332111272 M2I_Byrack_ReVeEnable_IMM17_24 "读取软件版本使能位_IMM17";
CM_ SG_ 2332111272 Reserved_24 "预留预留";
CM_ SG_ 2332111272 M2I_Byrack_IsPostTm_IMM17_24 "绝缘采样时间_IMM17";
CM_ SG_ 2332111272 M2I_Byrack_SysABStTm_IMM17_24 "电压稳定时间_IMM17";
CM_ SG_ 2332111273 CRC_M2I_Byrack_IMM17_25 "CRC校验_IMM17";
CM_ SG_ 2332111273 M2I_Byrack_HVS_IMM17_25 "绝缘测量电压_IMM17";
CM_ SG_ 2332111273 M2I_Byrack_Enable_IMM17_25 "绝缘采样使能位_IMM17";
CM_ SG_ 2332111273 M2I_Byrack_ReVeEnable_IMM17_25 "读取软件版本使能位_IMM17";
CM_ SG_ 2332111273 Reserved_25 "预留预留";
CM_ SG_ 2332111273 M2I_Byrack_IsPostTm_IMM17_25 "绝缘采样时间_IMM17";
CM_ SG_ 2332111273 M2I_Byrack_SysABStTm_IMM17_25 "电压稳定时间_IMM17";
CM_ SG_ 2332111274 CRC_M2I_Byrack_IMM17_26 "CRC校验_IMM17";
CM_ SG_ 2332111274 M2I_Byrack_HVS_IMM17_26 "绝缘测量电压_IMM17";
CM_ SG_ 2332111274 M2I_Byrack_Enable_IMM17_26 "绝缘采样使能位_IMM17";
CM_ SG_ 2332111274 M2I_Byrack_ReVeEnable_IMM17_26 "读取软件版本使能位_IMM17";
CM_ SG_ 2332111274 Reserved_26 "预留预留";
CM_ SG_ 2332111274 M2I_Byrack_IsPostTm_IMM17_26 "绝缘采样时间_IMM17";
CM_ SG_ 2332111274 M2I_Byrack_SysABStTm_IMM17_26 "电压稳定时间_IMM17";
CM_ SG_ 2332111275 CRC_M2I_Byrack_IMM17_27 "CRC校验_IMM17";
CM_ SG_ 2332111275 M2I_Byrack_HVS_IMM17_27 "绝缘测量电压_IMM17";
CM_ SG_ 2332111275 M2I_Byrack_Enable_IMM17_27 "绝缘采样使能位_IMM17";
CM_ SG_ 2332111275 M2I_Byrack_ReVeEnable_IMM17_27 "读取软件版本使能位_IMM17";
CM_ SG_ 2332111275 Reserved_27 "预留预留";
CM_ SG_ 2332111275 M2I_Byrack_IsPostTm_IMM17_27 "绝缘采样时间_IMM17";
CM_ SG_ 2332111275 M2I_Byrack_SysABStTm_IMM17_27 "电压稳定时间_IMM17";
CM_ SG_ 2332111276 CRC_M2I_Byrack_IMM17_28 "CRC校验_IMM17";
CM_ SG_ 2332111276 M2I_Byrack_HVS_IMM17_28 "绝缘测量电压_IMM17";
CM_ SG_ 2332111276 M2I_Byrack_Enable_IMM17_28 "绝缘采样使能位_IMM17";
CM_ SG_ 2332111276 M2I_Byrack_ReVeEnable_IMM17_28 "读取软件版本使能位_IMM17";
CM_ SG_ 2332111276 Reserved_28 "预留预留";
CM_ SG_ 2332111276 M2I_Byrack_IsPostTm_IMM17_28 "绝缘采样时间_IMM17";
CM_ SG_ 2332111276 M2I_Byrack_SysABStTm_IMM17_28 "电压稳定时间_IMM17";
CM_ SG_ 2332111277 CRC_M2I_Byrack_IMM17_29 "CRC校验_IMM17";
CM_ SG_ 2332111277 M2I_Byrack_HVS_IMM17_29 "绝缘测量电压_IMM17";
CM_ SG_ 2332111277 M2I_Byrack_Enable_IMM17_29 "绝缘采样使能位_IMM17";
CM_ SG_ 2332111277 M2I_Byrack_ReVeEnable_IMM17_29 "读取软件版本使能位_IMM17";
CM_ SG_ 2332111277 Reserved_29 "预留预留";
CM_ SG_ 2332111277 M2I_Byrack_IsPostTm_IMM17_29 "绝缘采样时间_IMM17";
CM_ SG_ 2332111277 M2I_Byrack_SysABStTm_IMM17_29 "电压稳定时间_IMM17";
CM_ SG_ 2332111278 CRC_M2I_Byrack_IMM17_30 "CRC校验_IMM17";
CM_ SG_ 2332111278 M2I_Byrack_HVS_IMM17_30 "绝缘测量电压_IMM17";
CM_ SG_ 2332111278 M2I_Byrack_Enable_IMM17_30 "绝缘采样使能位_IMM17";
CM_ SG_ 2332111278 M2I_Byrack_ReVeEnable_IMM17_30 "读取软件版本使能位_IMM17";
CM_ SG_ 2332111278 Reserved_30 "预留预留";
CM_ SG_ 2332111278 M2I_Byrack_IsPostTm_IMM17_30 "绝缘采样时间_IMM17";
CM_ SG_ 2332111278 M2I_Byrack_SysABStTm_IMM17_30 "电压稳定时间_IMM17";
CM_ SG_ 2332111279 CRC_M2I_Byrack_IMM17_31 "CRC校验_IMM17";
CM_ SG_ 2332111279 M2I_Byrack_HVS_IMM17_31 "绝缘测量电压_IMM17";
CM_ SG_ 2332111279 M2I_Byrack_Enable_IMM17_31 "绝缘采样使能位_IMM17";
CM_ SG_ 2332111279 M2I_Byrack_ReVeEnable_IMM17_31 "读取软件版本使能位_IMM17";
CM_ SG_ 2332111279 Reserved_31 "预留预留";
CM_ SG_ 2332111279 M2I_Byrack_IsPostTm_IMM17_31 "绝缘采样时间_IMM17";
CM_ SG_ 2332111279 M2I_Byrack_SysABStTm_IMM17_31 "电压稳定时间_IMM17";
CM_ SG_ 2332111505 CRC_M2I_Byrack_IMM18_01 "CRC校验_IMM18";
CM_ SG_ 2332111505 M2I_Byrack_HVS_IMM18_01 "绝缘测量电压_IMM18";
CM_ SG_ 2332111505 M2I_Byrack_Enable_IMM18_01 "绝缘采样使能位_IMM18";
CM_ SG_ 2332111505 M2I_Byrack_ReVeEnable_IMM18_01 "读取软件版本使能位_IMM18";
CM_ SG_ 2332111505 Reserved_01 "预留预留";
CM_ SG_ 2332111505 M2I_Byrack_IsPostTm_IMM18_01 "绝缘采样时间_IMM18";
CM_ SG_ 2332111505 M2I_Byrack_SysABStTm_IMM18_01 "电压稳定时间_IMM18";
CM_ SG_ 2332111506 CRC_M2I_Byrack_IMM18_02 "CRC校验_IMM18";
CM_ SG_ 2332111506 M2I_Byrack_HVS_IMM18_02 "绝缘测量电压_IMM18";
CM_ SG_ 2332111506 M2I_Byrack_Enable_IMM18_02 "绝缘采样使能位_IMM18";
CM_ SG_ 2332111506 M2I_Byrack_ReVeEnable_IMM18_02 "读取软件版本使能位_IMM18";
CM_ SG_ 2332111506 Reserved_02 "预留预留";
CM_ SG_ 2332111506 M2I_Byrack_IsPostTm_IMM18_02 "绝缘采样时间_IMM18";
CM_ SG_ 2332111506 M2I_Byrack_SysABStTm_IMM18_02 "电压稳定时间_IMM18";
CM_ SG_ 2332111507 CRC_M2I_Byrack_IMM18_03 "CRC校验_IMM18";
CM_ SG_ 2332111507 M2I_Byrack_HVS_IMM18_03 "绝缘测量电压_IMM18";
CM_ SG_ 2332111507 M2I_Byrack_Enable_IMM18_03 "绝缘采样使能位_IMM18";
CM_ SG_ 2332111507 M2I_Byrack_ReVeEnable_IMM18_03 "读取软件版本使能位_IMM18";
CM_ SG_ 2332111507 Reserved_03 "预留预留";
CM_ SG_ 2332111507 M2I_Byrack_IsPostTm_IMM18_03 "绝缘采样时间_IMM18";
CM_ SG_ 2332111507 M2I_Byrack_SysABStTm_IMM18_03 "电压稳定时间_IMM18";
CM_ SG_ 2332111508 CRC_M2I_Byrack_IMM18_04 "CRC校验_IMM18";
CM_ SG_ 2332111508 M2I_Byrack_HVS_IMM18_04 "绝缘测量电压_IMM18";
CM_ SG_ 2332111508 M2I_Byrack_Enable_IMM18_04 "绝缘采样使能位_IMM18";
CM_ SG_ 2332111508 M2I_Byrack_ReVeEnable_IMM18_04 "读取软件版本使能位_IMM18";
CM_ SG_ 2332111508 Reserved_04 "预留预留";
CM_ SG_ 2332111508 M2I_Byrack_IsPostTm_IMM18_04 "绝缘采样时间_IMM18";
CM_ SG_ 2332111508 M2I_Byrack_SysABStTm_IMM18_04 "电压稳定时间_IMM18";
CM_ SG_ 2332111509 CRC_M2I_Byrack_IMM18_05 "CRC校验_IMM18";
CM_ SG_ 2332111509 M2I_Byrack_HVS_IMM18_05 "绝缘测量电压_IMM18";
CM_ SG_ 2332111509 M2I_Byrack_Enable_IMM18_05 "绝缘采样使能位_IMM18";
CM_ SG_ 2332111509 M2I_Byrack_ReVeEnable_IMM18_05 "读取软件版本使能位_IMM18";
CM_ SG_ 2332111509 Reserved_05 "预留预留";
CM_ SG_ 2332111509 M2I_Byrack_IsPostTm_IMM18_05 "绝缘采样时间_IMM18";
CM_ SG_ 2332111509 M2I_Byrack_SysABStTm_IMM18_05 "电压稳定时间_IMM18";
CM_ SG_ 2332111510 CRC_M2I_Byrack_IMM18_06 "CRC校验_IMM18";
CM_ SG_ 2332111510 M2I_Byrack_HVS_IMM18_06 "绝缘测量电压_IMM18";
CM_ SG_ 2332111510 M2I_Byrack_Enable_IMM18_06 "绝缘采样使能位_IMM18";
CM_ SG_ 2332111510 M2I_Byrack_ReVeEnable_IMM18_06 "读取软件版本使能位_IMM18";
CM_ SG_ 2332111510 Reserved_06 "预留预留";
CM_ SG_ 2332111510 M2I_Byrack_IsPostTm_IMM18_06 "绝缘采样时间_IMM18";
CM_ SG_ 2332111510 M2I_Byrack_SysABStTm_IMM18_06 "电压稳定时间_IMM18";
CM_ SG_ 2332111511 CRC_M2I_Byrack_IMM18_07 "CRC校验_IMM18";
CM_ SG_ 2332111511 M2I_Byrack_HVS_IMM18_07 "绝缘测量电压_IMM18";
CM_ SG_ 2332111511 M2I_Byrack_Enable_IMM18_07 "绝缘采样使能位_IMM18";
CM_ SG_ 2332111511 M2I_Byrack_ReVeEnable_IMM18_07 "读取软件版本使能位_IMM18";
CM_ SG_ 2332111511 Reserved_07 "预留预留";
CM_ SG_ 2332111511 M2I_Byrack_IsPostTm_IMM18_07 "绝缘采样时间_IMM18";
CM_ SG_ 2332111511 M2I_Byrack_SysABStTm_IMM18_07 "电压稳定时间_IMM18";
CM_ SG_ 2332111512 CRC_M2I_Byrack_IMM18_08 "CRC校验_IMM18";
CM_ SG_ 2332111512 M2I_Byrack_HVS_IMM18_08 "绝缘测量电压_IMM18";
CM_ SG_ 2332111512 M2I_Byrack_Enable_IMM18_08 "绝缘采样使能位_IMM18";
CM_ SG_ 2332111512 M2I_Byrack_ReVeEnable_IMM18_08 "读取软件版本使能位_IMM18";
CM_ SG_ 2332111512 Reserved_08 "预留预留";
CM_ SG_ 2332111512 M2I_Byrack_IsPostTm_IMM18_08 "绝缘采样时间_IMM18";
CM_ SG_ 2332111512 M2I_Byrack_SysABStTm_IMM18_08 "电压稳定时间_IMM18";
CM_ SG_ 2332111513 CRC_M2I_Byrack_IMM18_09 "CRC校验_IMM18";
CM_ SG_ 2332111513 M2I_Byrack_HVS_IMM18_09 "绝缘测量电压_IMM18";
CM_ SG_ 2332111513 M2I_Byrack_Enable_IMM18_09 "绝缘采样使能位_IMM18";
CM_ SG_ 2332111513 M2I_Byrack_ReVeEnable_IMM18_09 "读取软件版本使能位_IMM18";
CM_ SG_ 2332111513 Reserved_09 "预留预留";
CM_ SG_ 2332111513 M2I_Byrack_IsPostTm_IMM18_09 "绝缘采样时间_IMM18";
CM_ SG_ 2332111513 M2I_Byrack_SysABStTm_IMM18_09 "电压稳定时间_IMM18";
CM_ SG_ 2332111514 CRC_M2I_Byrack_IMM18_10 "CRC校验_IMM18";
CM_ SG_ 2332111514 M2I_Byrack_HVS_IMM18_10 "绝缘测量电压_IMM18";
CM_ SG_ 2332111514 M2I_Byrack_Enable_IMM18_10 "绝缘采样使能位_IMM18";
CM_ SG_ 2332111514 M2I_Byrack_ReVeEnable_IMM18_10 "读取软件版本使能位_IMM18";
CM_ SG_ 2332111514 Reserved_10 "预留预留";
CM_ SG_ 2332111514 M2I_Byrack_IsPostTm_IMM18_10 "绝缘采样时间_IMM18";
CM_ SG_ 2332111514 M2I_Byrack_SysABStTm_IMM18_10 "电压稳定时间_IMM18";
CM_ SG_ 2332111515 CRC_M2I_Byrack_IMM18_11 "CRC校验_IMM18";
CM_ SG_ 2332111515 M2I_Byrack_HVS_IMM18_11 "绝缘测量电压_IMM18";
CM_ SG_ 2332111515 M2I_Byrack_Enable_IMM18_11 "绝缘采样使能位_IMM18";
CM_ SG_ 2332111515 M2I_Byrack_ReVeEnable_IMM18_11 "读取软件版本使能位_IMM18";
CM_ SG_ 2332111515 Reserved_11 "预留预留";
CM_ SG_ 2332111515 M2I_Byrack_IsPostTm_IMM18_11 "绝缘采样时间_IMM18";
CM_ SG_ 2332111515 M2I_Byrack_SysABStTm_IMM18_11 "电压稳定时间_IMM18";
CM_ SG_ 2332111516 CRC_M2I_Byrack_IMM18_12 "CRC校验_IMM18";
CM_ SG_ 2332111516 M2I_Byrack_HVS_IMM18_12 "绝缘测量电压_IMM18";
CM_ SG_ 2332111516 M2I_Byrack_Enable_IMM18_12 "绝缘采样使能位_IMM18";
CM_ SG_ 2332111516 M2I_Byrack_ReVeEnable_IMM18_12 "读取软件版本使能位_IMM18";
CM_ SG_ 2332111516 Reserved_12 "预留预留";
CM_ SG_ 2332111516 M2I_Byrack_IsPostTm_IMM18_12 "绝缘采样时间_IMM18";
CM_ SG_ 2332111516 M2I_Byrack_SysABStTm_IMM18_12 "电压稳定时间_IMM18";
CM_ SG_ 2332111517 CRC_M2I_Byrack_IMM18_13 "CRC校验_IMM18";
CM_ SG_ 2332111517 M2I_Byrack_HVS_IMM18_13 "绝缘测量电压_IMM18";
CM_ SG_ 2332111517 M2I_Byrack_Enable_IMM18_13 "绝缘采样使能位_IMM18";
CM_ SG_ 2332111517 M2I_Byrack_ReVeEnable_IMM18_13 "读取软件版本使能位_IMM18";
CM_ SG_ 2332111517 Reserved_13 "预留预留";
CM_ SG_ 2332111517 M2I_Byrack_IsPostTm_IMM18_13 "绝缘采样时间_IMM18";
CM_ SG_ 2332111517 M2I_Byrack_SysABStTm_IMM18_13 "电压稳定时间_IMM18";
CM_ SG_ 2332111518 CRC_M2I_Byrack_IMM18_14 "CRC校验_IMM18";
CM_ SG_ 2332111518 M2I_Byrack_HVS_IMM18_14 "绝缘测量电压_IMM18";
CM_ SG_ 2332111518 M2I_Byrack_Enable_IMM18_14 "绝缘采样使能位_IMM18";
CM_ SG_ 2332111518 M2I_Byrack_ReVeEnable_IMM18_14 "读取软件版本使能位_IMM18";
CM_ SG_ 2332111518 Reserved_14 "预留预留";
CM_ SG_ 2332111518 M2I_Byrack_IsPostTm_IMM18_14 "绝缘采样时间_IMM18";
CM_ SG_ 2332111518 M2I_Byrack_SysABStTm_IMM18_14 "电压稳定时间_IMM18";
CM_ SG_ 2332111519 CRC_M2I_Byrack_IMM18_15 "CRC校验_IMM18";
CM_ SG_ 2332111519 M2I_Byrack_HVS_IMM18_15 "绝缘测量电压_IMM18";
CM_ SG_ 2332111519 M2I_Byrack_Enable_IMM18_15 "绝缘采样使能位_IMM18";
CM_ SG_ 2332111519 M2I_Byrack_ReVeEnable_IMM18_15 "读取软件版本使能位_IMM18";
CM_ SG_ 2332111519 Reserved_15 "预留预留";
CM_ SG_ 2332111519 M2I_Byrack_IsPostTm_IMM18_15 "绝缘采样时间_IMM18";
CM_ SG_ 2332111519 M2I_Byrack_SysABStTm_IMM18_15 "电压稳定时间_IMM18";
CM_ SG_ 2332111520 CRC_M2I_Byrack_IMM18_16 "CRC校验_IMM18";
CM_ SG_ 2332111520 M2I_Byrack_HVS_IMM18_16 "绝缘测量电压_IMM18";
CM_ SG_ 2332111520 M2I_Byrack_Enable_IMM18_16 "绝缘采样使能位_IMM18";
CM_ SG_ 2332111520 M2I_Byrack_ReVeEnable_IMM18_16 "读取软件版本使能位_IMM18";
CM_ SG_ 2332111520 Reserved_16 "预留预留";
CM_ SG_ 2332111520 M2I_Byrack_IsPostTm_IMM18_16 "绝缘采样时间_IMM18";
CM_ SG_ 2332111520 M2I_Byrack_SysABStTm_IMM18_16 "电压稳定时间_IMM18";
CM_ SG_ 2332111521 CRC_M2I_Byrack_IMM18_17 "CRC校验_IMM18";
CM_ SG_ 2332111521 M2I_Byrack_HVS_IMM18_17 "绝缘测量电压_IMM18";
CM_ SG_ 2332111521 M2I_Byrack_Enable_IMM18_17 "绝缘采样使能位_IMM18";
CM_ SG_ 2332111521 M2I_Byrack_ReVeEnable_IMM18_17 "读取软件版本使能位_IMM18";
CM_ SG_ 2332111521 Reserved_17 "预留预留";
CM_ SG_ 2332111521 M2I_Byrack_IsPostTm_IMM18_17 "绝缘采样时间_IMM18";
CM_ SG_ 2332111521 M2I_Byrack_SysABStTm_IMM18_17 "电压稳定时间_IMM18";
CM_ SG_ 2332111522 CRC_M2I_Byrack_IMM18_18 "CRC校验_IMM18";
CM_ SG_ 2332111522 M2I_Byrack_HVS_IMM18_18 "绝缘测量电压_IMM18";
CM_ SG_ 2332111522 M2I_Byrack_Enable_IMM18_18 "绝缘采样使能位_IMM18";
CM_ SG_ 2332111522 M2I_Byrack_ReVeEnable_IMM18_18 "读取软件版本使能位_IMM18";
CM_ SG_ 2332111522 Reserved_18 "预留预留";
CM_ SG_ 2332111522 M2I_Byrack_IsPostTm_IMM18_18 "绝缘采样时间_IMM18";
CM_ SG_ 2332111522 M2I_Byrack_SysABStTm_IMM18_18 "电压稳定时间_IMM18";
CM_ SG_ 2332111523 CRC_M2I_Byrack_IMM18_19 "CRC校验_IMM18";
CM_ SG_ 2332111523 M2I_Byrack_HVS_IMM18_19 "绝缘测量电压_IMM18";
CM_ SG_ 2332111523 M2I_Byrack_Enable_IMM18_19 "绝缘采样使能位_IMM18";
CM_ SG_ 2332111523 M2I_Byrack_ReVeEnable_IMM18_19 "读取软件版本使能位_IMM18";
CM_ SG_ 2332111523 Reserved_19 "预留预留";
CM_ SG_ 2332111523 M2I_Byrack_IsPostTm_IMM18_19 "绝缘采样时间_IMM18";
CM_ SG_ 2332111523 M2I_Byrack_SysABStTm_IMM18_19 "电压稳定时间_IMM18";
CM_ SG_ 2332111524 CRC_M2I_Byrack_IMM18_20 "CRC校验_IMM18";
CM_ SG_ 2332111524 M2I_Byrack_HVS_IMM18_20 "绝缘测量电压_IMM18";
CM_ SG_ 2332111524 M2I_Byrack_Enable_IMM18_20 "绝缘采样使能位_IMM18";
CM_ SG_ 2332111524 M2I_Byrack_ReVeEnable_IMM18_20 "读取软件版本使能位_IMM18";
CM_ SG_ 2332111524 Reserved_20 "预留预留";
CM_ SG_ 2332111524 M2I_Byrack_IsPostTm_IMM18_20 "绝缘采样时间_IMM18";
CM_ SG_ 2332111524 M2I_Byrack_SysABStTm_IMM18_20 "电压稳定时间_IMM18";
CM_ SG_ 2332111525 CRC_M2I_Byrack_IMM18_21 "CRC校验_IMM18";
CM_ SG_ 2332111525 M2I_Byrack_HVS_IMM18_21 "绝缘测量电压_IMM18";
CM_ SG_ 2332111525 M2I_Byrack_Enable_IMM18_21 "绝缘采样使能位_IMM18";
CM_ SG_ 2332111525 M2I_Byrack_ReVeEnable_IMM18_21 "读取软件版本使能位_IMM18";
CM_ SG_ 2332111525 Reserved_21 "预留预留";
CM_ SG_ 2332111525 M2I_Byrack_IsPostTm_IMM18_21 "绝缘采样时间_IMM18";
CM_ SG_ 2332111525 M2I_Byrack_SysABStTm_IMM18_21 "电压稳定时间_IMM18";
CM_ SG_ 2332111526 CRC_M2I_Byrack_IMM18_22 "CRC校验_IMM18";
CM_ SG_ 2332111526 M2I_Byrack_HVS_IMM18_22 "绝缘测量电压_IMM18";
CM_ SG_ 2332111526 M2I_Byrack_Enable_IMM18_22 "绝缘采样使能位_IMM18";
CM_ SG_ 2332111526 M2I_Byrack_ReVeEnable_IMM18_22 "读取软件版本使能位_IMM18";
CM_ SG_ 2332111526 Reserved_22 "预留预留";
CM_ SG_ 2332111526 M2I_Byrack_IsPostTm_IMM18_22 "绝缘采样时间_IMM18";
CM_ SG_ 2332111526 M2I_Byrack_SysABStTm_IMM18_22 "电压稳定时间_IMM18";
CM_ SG_ 2332111527 CRC_M2I_Byrack_IMM18_23 "CRC校验_IMM18";
CM_ SG_ 2332111527 M2I_Byrack_HVS_IMM18_23 "绝缘测量电压_IMM18";
CM_ SG_ 2332111527 M2I_Byrack_Enable_IMM18_23 "绝缘采样使能位_IMM18";
CM_ SG_ 2332111527 M2I_Byrack_ReVeEnable_IMM18_23 "读取软件版本使能位_IMM18";
CM_ SG_ 2332111527 Reserved_23 "预留预留";
CM_ SG_ 2332111527 M2I_Byrack_IsPostTm_IMM18_23 "绝缘采样时间_IMM18";
CM_ SG_ 2332111527 M2I_Byrack_SysABStTm_IMM18_23 "电压稳定时间_IMM18";
CM_ SG_ 2332111528 CRC_M2I_Byrack_IMM18_24 "CRC校验_IMM18";
CM_ SG_ 2332111528 M2I_Byrack_HVS_IMM18_24 "绝缘测量电压_IMM18";
CM_ SG_ 2332111528 M2I_Byrack_Enable_IMM18_24 "绝缘采样使能位_IMM18";
CM_ SG_ 2332111528 M2I_Byrack_ReVeEnable_IMM18_24 "读取软件版本使能位_IMM18";
CM_ SG_ 2332111528 Reserved_24 "预留预留";
CM_ SG_ 2332111528 M2I_Byrack_IsPostTm_IMM18_24 "绝缘采样时间_IMM18";
CM_ SG_ 2332111528 M2I_Byrack_SysABStTm_IMM18_24 "电压稳定时间_IMM18";
CM_ SG_ 2332111529 CRC_M2I_Byrack_IMM18_25 "CRC校验_IMM18";
CM_ SG_ 2332111529 M2I_Byrack_HVS_IMM18_25 "绝缘测量电压_IMM18";
CM_ SG_ 2332111529 M2I_Byrack_Enable_IMM18_25 "绝缘采样使能位_IMM18";
CM_ SG_ 2332111529 M2I_Byrack_ReVeEnable_IMM18_25 "读取软件版本使能位_IMM18";
CM_ SG_ 2332111529 Reserved_25 "预留预留";
CM_ SG_ 2332111529 M2I_Byrack_IsPostTm_IMM18_25 "绝缘采样时间_IMM18";
CM_ SG_ 2332111529 M2I_Byrack_SysABStTm_IMM18_25 "电压稳定时间_IMM18";
CM_ SG_ 2332111530 CRC_M2I_Byrack_IMM18_26 "CRC校验_IMM18";
CM_ SG_ 2332111530 M2I_Byrack_HVS_IMM18_26 "绝缘测量电压_IMM18";
CM_ SG_ 2332111530 M2I_Byrack_Enable_IMM18_26 "绝缘采样使能位_IMM18";
CM_ SG_ 2332111530 M2I_Byrack_ReVeEnable_IMM18_26 "读取软件版本使能位_IMM18";
CM_ SG_ 2332111530 Reserved_26 "预留预留";
CM_ SG_ 2332111530 M2I_Byrack_IsPostTm_IMM18_26 "绝缘采样时间_IMM18";
CM_ SG_ 2332111530 M2I_Byrack_SysABStTm_IMM18_26 "电压稳定时间_IMM18";
CM_ SG_ 2332111531 CRC_M2I_Byrack_IMM18_27 "CRC校验_IMM18";
CM_ SG_ 2332111531 M2I_Byrack_HVS_IMM18_27 "绝缘测量电压_IMM18";
CM_ SG_ 2332111531 M2I_Byrack_Enable_IMM18_27 "绝缘采样使能位_IMM18";
CM_ SG_ 2332111531 M2I_Byrack_ReVeEnable_IMM18_27 "读取软件版本使能位_IMM18";
CM_ SG_ 2332111531 Reserved_27 "预留预留";
CM_ SG_ 2332111531 M2I_Byrack_IsPostTm_IMM18_27 "绝缘采样时间_IMM18";
CM_ SG_ 2332111531 M2I_Byrack_SysABStTm_IMM18_27 "电压稳定时间_IMM18";
CM_ SG_ 2332111532 CRC_M2I_Byrack_IMM18_28 "CRC校验_IMM18";
CM_ SG_ 2332111532 M2I_Byrack_HVS_IMM18_28 "绝缘测量电压_IMM18";
CM_ SG_ 2332111532 M2I_Byrack_Enable_IMM18_28 "绝缘采样使能位_IMM18";
CM_ SG_ 2332111532 M2I_Byrack_ReVeEnable_IMM18_28 "读取软件版本使能位_IMM18";
CM_ SG_ 2332111532 Reserved_28 "预留预留";
CM_ SG_ 2332111532 M2I_Byrack_IsPostTm_IMM18_28 "绝缘采样时间_IMM18";
CM_ SG_ 2332111532 M2I_Byrack_SysABStTm_IMM18_28 "电压稳定时间_IMM18";
CM_ SG_ 2332111533 CRC_M2I_Byrack_IMM18_29 "CRC校验_IMM18";
CM_ SG_ 2332111533 M2I_Byrack_HVS_IMM18_29 "绝缘测量电压_IMM18";
CM_ SG_ 2332111533 M2I_Byrack_Enable_IMM18_29 "绝缘采样使能位_IMM18";
CM_ SG_ 2332111533 M2I_Byrack_ReVeEnable_IMM18_29 "读取软件版本使能位_IMM18";
CM_ SG_ 2332111533 Reserved_29 "预留预留";
CM_ SG_ 2332111533 M2I_Byrack_IsPostTm_IMM18_29 "绝缘采样时间_IMM18";
CM_ SG_ 2332111533 M2I_Byrack_SysABStTm_IMM18_29 "电压稳定时间_IMM18";
CM_ SG_ 2332111534 CRC_M2I_Byrack_IMM18_30 "CRC校验_IMM18";
CM_ SG_ 2332111534 M2I_Byrack_HVS_IMM18_30 "绝缘测量电压_IMM18";
CM_ SG_ 2332111534 M2I_Byrack_Enable_IMM18_30 "绝缘采样使能位_IMM18";
CM_ SG_ 2332111534 M2I_Byrack_ReVeEnable_IMM18_30 "读取软件版本使能位_IMM18";
CM_ SG_ 2332111534 Reserved_30 "预留预留";
CM_ SG_ 2332111534 M2I_Byrack_IsPostTm_IMM18_30 "绝缘采样时间_IMM18";
CM_ SG_ 2332111534 M2I_Byrack_SysABStTm_IMM18_30 "电压稳定时间_IMM18";
CM_ SG_ 2332111535 CRC_M2I_Byrack_IMM18_31 "CRC校验_IMM18";
CM_ SG_ 2332111535 M2I_Byrack_HVS_IMM18_31 "绝缘测量电压_IMM18";
CM_ SG_ 2332111535 M2I_Byrack_Enable_IMM18_31 "绝缘采样使能位_IMM18";
CM_ SG_ 2332111535 M2I_Byrack_ReVeEnable_IMM18_31 "读取软件版本使能位_IMM18";
CM_ SG_ 2332111535 Reserved_31 "预留预留";
CM_ SG_ 2332111535 M2I_Byrack_IsPostTm_IMM18_31 "绝缘采样时间_IMM18";
CM_ SG_ 2332111535 M2I_Byrack_SysABStTm_IMM18_31 "电压稳定时间_IMM18";
CM_ SG_ 2332111761 CRC_M2I_Byrack_IMM19_01 "CRC校验_IMM19";
CM_ SG_ 2332111761 M2I_Byrack_HVS_IMM19_01 "绝缘测量电压_IMM19";
CM_ SG_ 2332111761 M2I_Byrack_Enable_IMM9_01 "绝缘采样使能位_IMM19";
CM_ SG_ 2332111761 M2I_Byrack_ReVeEnable_IMM19_01 "读取软件版本使能位_IMM19";
CM_ SG_ 2332111761 Reserved_01 "预留预留";
CM_ SG_ 2332111761 M2I_Byrack_IsPostTm_IMM19_01 "绝缘采样时间_IMM19";
CM_ SG_ 2332111761 M2I_Byrack_SysABStTm_IMM19_01 "电压稳定时间_IMM19";
CM_ SG_ 2332111762 CRC_M2I_Byrack_IMM19_02 "CRC校验_IMM19";
CM_ SG_ 2332111762 M2I_Byrack_HVS_IMM19_02 "绝缘测量电压_IMM19";
CM_ SG_ 2332111762 M2I_Byrack_Enable_IMM9_02 "绝缘采样使能位_IMM19";
CM_ SG_ 2332111762 M2I_Byrack_ReVeEnable_IMM19_02 "读取软件版本使能位_IMM19";
CM_ SG_ 2332111762 Reserved_02 "预留预留";
CM_ SG_ 2332111762 M2I_Byrack_IsPostTm_IMM19_02 "绝缘采样时间_IMM19";
CM_ SG_ 2332111762 M2I_Byrack_SysABStTm_IMM19_02 "电压稳定时间_IMM19";
CM_ SG_ 2332111763 CRC_M2I_Byrack_IMM19_03 "CRC校验_IMM19";
CM_ SG_ 2332111763 M2I_Byrack_HVS_IMM19_03 "绝缘测量电压_IMM19";
CM_ SG_ 2332111763 M2I_Byrack_Enable_IMM9_03 "绝缘采样使能位_IMM19";
CM_ SG_ 2332111763 M2I_Byrack_ReVeEnable_IMM19_03 "读取软件版本使能位_IMM19";
CM_ SG_ 2332111763 Reserved_03 "预留预留";
CM_ SG_ 2332111763 M2I_Byrack_IsPostTm_IMM19_03 "绝缘采样时间_IMM19";
CM_ SG_ 2332111763 M2I_Byrack_SysABStTm_IMM19_03 "电压稳定时间_IMM19";
CM_ SG_ 2332111764 CRC_M2I_Byrack_IMM19_04 "CRC校验_IMM19";
CM_ SG_ 2332111764 M2I_Byrack_HVS_IMM19_04 "绝缘测量电压_IMM19";
CM_ SG_ 2332111764 M2I_Byrack_Enable_IMM9_04 "绝缘采样使能位_IMM19";
CM_ SG_ 2332111764 M2I_Byrack_ReVeEnable_IMM19_04 "读取软件版本使能位_IMM19";
CM_ SG_ 2332111764 Reserved_04 "预留预留";
CM_ SG_ 2332111764 M2I_Byrack_IsPostTm_IMM19_04 "绝缘采样时间_IMM19";
CM_ SG_ 2332111764 M2I_Byrack_SysABStTm_IMM19_04 "电压稳定时间_IMM19";
CM_ SG_ 2332111765 CRC_M2I_Byrack_IMM19_05 "CRC校验_IMM19";
CM_ SG_ 2332111765 M2I_Byrack_HVS_IMM19_05 "绝缘测量电压_IMM19";
CM_ SG_ 2332111765 M2I_Byrack_Enable_IMM9_05 "绝缘采样使能位_IMM19";
CM_ SG_ 2332111765 M2I_Byrack_ReVeEnable_IMM19_05 "读取软件版本使能位_IMM19";
CM_ SG_ 2332111765 Reserved_05 "预留预留";
CM_ SG_ 2332111765 M2I_Byrack_IsPostTm_IMM19_05 "绝缘采样时间_IMM19";
CM_ SG_ 2332111765 M2I_Byrack_SysABStTm_IMM19_05 "电压稳定时间_IMM19";
CM_ SG_ 2332111766 CRC_M2I_Byrack_IMM19_06 "CRC校验_IMM19";
CM_ SG_ 2332111766 M2I_Byrack_HVS_IMM19_06 "绝缘测量电压_IMM19";
CM_ SG_ 2332111766 M2I_Byrack_Enable_IMM9_06 "绝缘采样使能位_IMM19";
CM_ SG_ 2332111766 M2I_Byrack_ReVeEnable_IMM19_06 "读取软件版本使能位_IMM19";
CM_ SG_ 2332111766 Reserved_06 "预留预留";
CM_ SG_ 2332111766 M2I_Byrack_IsPostTm_IMM19_06 "绝缘采样时间_IMM19";
CM_ SG_ 2332111766 M2I_Byrack_SysABStTm_IMM19_06 "电压稳定时间_IMM19";
CM_ SG_ 2332111767 CRC_M2I_Byrack_IMM19_07 "CRC校验_IMM19";
CM_ SG_ 2332111767 M2I_Byrack_HVS_IMM19_07 "绝缘测量电压_IMM19";
CM_ SG_ 2332111767 M2I_Byrack_Enable_IMM9_07 "绝缘采样使能位_IMM19";
CM_ SG_ 2332111767 M2I_Byrack_ReVeEnable_IMM19_07 "读取软件版本使能位_IMM19";
CM_ SG_ 2332111767 Reserved_07 "预留预留";
CM_ SG_ 2332111767 M2I_Byrack_IsPostTm_IMM19_07 "绝缘采样时间_IMM19";
CM_ SG_ 2332111767 M2I_Byrack_SysABStTm_IMM19_07 "电压稳定时间_IMM19";
CM_ SG_ 2332111768 CRC_M2I_Byrack_IMM19_08 "CRC校验_IMM19";
CM_ SG_ 2332111768 M2I_Byrack_HVS_IMM19_08 "绝缘测量电压_IMM19";
CM_ SG_ 2332111768 M2I_Byrack_Enable_IMM9_08 "绝缘采样使能位_IMM19";
CM_ SG_ 2332111768 M2I_Byrack_ReVeEnable_IMM19_08 "读取软件版本使能位_IMM19";
CM_ SG_ 2332111768 Reserved_08 "预留预留";
CM_ SG_ 2332111768 M2I_Byrack_IsPostTm_IMM19_08 "绝缘采样时间_IMM19";
CM_ SG_ 2332111768 M2I_Byrack_SysABStTm_IMM19_08 "电压稳定时间_IMM19";
CM_ SG_ 2332111769 CRC_M2I_Byrack_IMM19_09 "CRC校验_IMM19";
CM_ SG_ 2332111769 M2I_Byrack_HVS_IMM19_09 "绝缘测量电压_IMM19";
CM_ SG_ 2332111769 M2I_Byrack_Enable_IMM9_09 "绝缘采样使能位_IMM19";
CM_ SG_ 2332111769 M2I_Byrack_ReVeEnable_IMM19_09 "读取软件版本使能位_IMM19";
CM_ SG_ 2332111769 Reserved_09 "预留预留";
CM_ SG_ 2332111769 M2I_Byrack_IsPostTm_IMM19_09 "绝缘采样时间_IMM19";
CM_ SG_ 2332111769 M2I_Byrack_SysABStTm_IMM19_09 "电压稳定时间_IMM19";
CM_ SG_ 2332111770 CRC_M2I_Byrack_IMM19_10 "CRC校验_IMM19";
CM_ SG_ 2332111770 M2I_Byrack_HVS_IMM19_10 "绝缘测量电压_IMM19";
CM_ SG_ 2332111770 M2I_Byrack_Enable_IMM9_10 "绝缘采样使能位_IMM19";
CM_ SG_ 2332111770 M2I_Byrack_ReVeEnable_IMM19_10 "读取软件版本使能位_IMM19";
CM_ SG_ 2332111770 Reserved_10 "预留预留";
CM_ SG_ 2332111770 M2I_Byrack_IsPostTm_IMM19_10 "绝缘采样时间_IMM19";
CM_ SG_ 2332111770 M2I_Byrack_SysABStTm_IMM19_10 "电压稳定时间_IMM19";
CM_ SG_ 2332111771 CRC_M2I_Byrack_IMM19_11 "CRC校验_IMM19";
CM_ SG_ 2332111771 M2I_Byrack_HVS_IMM19_11 "绝缘测量电压_IMM19";
CM_ SG_ 2332111771 M2I_Byrack_Enable_IMM9_11 "绝缘采样使能位_IMM19";
CM_ SG_ 2332111771 M2I_Byrack_ReVeEnable_IMM19_11 "读取软件版本使能位_IMM19";
CM_ SG_ 2332111771 Reserved_11 "预留预留";
CM_ SG_ 2332111771 M2I_Byrack_IsPostTm_IMM19_11 "绝缘采样时间_IMM19";
CM_ SG_ 2332111771 M2I_Byrack_SysABStTm_IMM19_11 "电压稳定时间_IMM19";
CM_ SG_ 2332111772 CRC_M2I_Byrack_IMM19_12 "CRC校验_IMM19";
CM_ SG_ 2332111772 M2I_Byrack_HVS_IMM19_12 "绝缘测量电压_IMM19";
CM_ SG_ 2332111772 M2I_Byrack_Enable_IMM9_12 "绝缘采样使能位_IMM19";
CM_ SG_ 2332111772 M2I_Byrack_ReVeEnable_IMM19_12 "读取软件版本使能位_IMM19";
CM_ SG_ 2332111772 Reserved_12 "预留预留";
CM_ SG_ 2332111772 M2I_Byrack_IsPostTm_IMM19_12 "绝缘采样时间_IMM19";
CM_ SG_ 2332111772 M2I_Byrack_SysABStTm_IMM19_12 "电压稳定时间_IMM19";
CM_ SG_ 2332111773 CRC_M2I_Byrack_IMM19_13 "CRC校验_IMM19";
CM_ SG_ 2332111773 M2I_Byrack_HVS_IMM19_13 "绝缘测量电压_IMM19";
CM_ SG_ 2332111773 M2I_Byrack_Enable_IMM9_13 "绝缘采样使能位_IMM19";
CM_ SG_ 2332111773 M2I_Byrack_ReVeEnable_IMM19_13 "读取软件版本使能位_IMM19";
CM_ SG_ 2332111773 Reserved_13 "预留预留";
CM_ SG_ 2332111773 M2I_Byrack_IsPostTm_IMM19_13 "绝缘采样时间_IMM19";
CM_ SG_ 2332111773 M2I_Byrack_SysABStTm_IMM19_13 "电压稳定时间_IMM19";
CM_ SG_ 2332111774 CRC_M2I_Byrack_IMM19_14 "CRC校验_IMM19";
CM_ SG_ 2332111774 M2I_Byrack_HVS_IMM19_14 "绝缘测量电压_IMM19";
CM_ SG_ 2332111774 M2I_Byrack_Enable_IMM9_14 "绝缘采样使能位_IMM19";
CM_ SG_ 2332111774 M2I_Byrack_ReVeEnable_IMM19_14 "读取软件版本使能位_IMM19";
CM_ SG_ 2332111774 Reserved_14 "预留预留";
CM_ SG_ 2332111774 M2I_Byrack_IsPostTm_IMM19_14 "绝缘采样时间_IMM19";
CM_ SG_ 2332111774 M2I_Byrack_SysABStTm_IMM19_14 "电压稳定时间_IMM19";
CM_ SG_ 2332111775 CRC_M2I_Byrack_IMM19_15 "CRC校验_IMM19";
CM_ SG_ 2332111775 M2I_Byrack_HVS_IMM19_15 "绝缘测量电压_IMM19";
CM_ SG_ 2332111775 M2I_Byrack_Enable_IMM9_15 "绝缘采样使能位_IMM19";
CM_ SG_ 2332111775 M2I_Byrack_ReVeEnable_IMM19_15 "读取软件版本使能位_IMM19";
CM_ SG_ 2332111775 Reserved_15 "预留预留";
CM_ SG_ 2332111775 M2I_Byrack_IsPostTm_IMM19_15 "绝缘采样时间_IMM19";
CM_ SG_ 2332111775 M2I_Byrack_SysABStTm_IMM19_15 "电压稳定时间_IMM19";
CM_ SG_ 2332111776 CRC_M2I_Byrack_IMM19_16 "CRC校验_IMM19";
CM_ SG_ 2332111776 M2I_Byrack_HVS_IMM19_16 "绝缘测量电压_IMM19";
CM_ SG_ 2332111776 M2I_Byrack_Enable_IMM9_16 "绝缘采样使能位_IMM19";
CM_ SG_ 2332111776 M2I_Byrack_ReVeEnable_IMM19_16 "读取软件版本使能位_IMM19";
CM_ SG_ 2332111776 Reserved_16 "预留预留";
CM_ SG_ 2332111776 M2I_Byrack_IsPostTm_IMM19_16 "绝缘采样时间_IMM19";
CM_ SG_ 2332111776 M2I_Byrack_SysABStTm_IMM19_16 "电压稳定时间_IMM19";
CM_ SG_ 2332111777 CRC_M2I_Byrack_IMM19_17 "CRC校验_IMM19";
CM_ SG_ 2332111777 M2I_Byrack_HVS_IMM19_17 "绝缘测量电压_IMM19";
CM_ SG_ 2332111777 M2I_Byrack_Enable_IMM9_17 "绝缘采样使能位_IMM19";
CM_ SG_ 2332111777 M2I_Byrack_ReVeEnable_IMM19_17 "读取软件版本使能位_IMM19";
CM_ SG_ 2332111777 Reserved_17 "预留预留";
CM_ SG_ 2332111777 M2I_Byrack_IsPostTm_IMM19_17 "绝缘采样时间_IMM19";
CM_ SG_ 2332111777 M2I_Byrack_SysABStTm_IMM19_17 "电压稳定时间_IMM19";
CM_ SG_ 2332111778 CRC_M2I_Byrack_IMM19_18 "CRC校验_IMM19";
CM_ SG_ 2332111778 M2I_Byrack_HVS_IMM19_18 "绝缘测量电压_IMM19";
CM_ SG_ 2332111778 M2I_Byrack_Enable_IMM9_18 "绝缘采样使能位_IMM19";
CM_ SG_ 2332111778 M2I_Byrack_ReVeEnable_IMM19_18 "读取软件版本使能位_IMM19";
CM_ SG_ 2332111778 Reserved_18 "预留预留";
CM_ SG_ 2332111778 M2I_Byrack_IsPostTm_IMM19_18 "绝缘采样时间_IMM19";
CM_ SG_ 2332111778 M2I_Byrack_SysABStTm_IMM19_18 "电压稳定时间_IMM19";
CM_ SG_ 2332111779 CRC_M2I_Byrack_IMM19_19 "CRC校验_IMM19";
CM_ SG_ 2332111779 M2I_Byrack_HVS_IMM19_19 "绝缘测量电压_IMM19";
CM_ SG_ 2332111779 M2I_Byrack_Enable_IMM9_19 "绝缘采样使能位_IMM19";
CM_ SG_ 2332111779 M2I_Byrack_ReVeEnable_IMM19_19 "读取软件版本使能位_IMM19";
CM_ SG_ 2332111779 Reserved_19 "预留预留";
CM_ SG_ 2332111779 M2I_Byrack_IsPostTm_IMM19_19 "绝缘采样时间_IMM19";
CM_ SG_ 2332111779 M2I_Byrack_SysABStTm_IMM19_19 "电压稳定时间_IMM19";
CM_ SG_ 2332111780 CRC_M2I_Byrack_IMM19_20 "CRC校验_IMM19";
CM_ SG_ 2332111780 M2I_Byrack_HVS_IMM19_20 "绝缘测量电压_IMM19";
CM_ SG_ 2332111780 M2I_Byrack_Enable_IMM9_20 "绝缘采样使能位_IMM19";
CM_ SG_ 2332111780 M2I_Byrack_ReVeEnable_IMM19_20 "读取软件版本使能位_IMM19";
CM_ SG_ 2332111780 Reserved_20 "预留预留";
CM_ SG_ 2332111780 M2I_Byrack_IsPostTm_IMM19_20 "绝缘采样时间_IMM19";
CM_ SG_ 2332111780 M2I_Byrack_SysABStTm_IMM19_20 "电压稳定时间_IMM19";
CM_ SG_ 2332111781 CRC_M2I_Byrack_IMM19_21 "CRC校验_IMM19";
CM_ SG_ 2332111781 M2I_Byrack_HVS_IMM19_21 "绝缘测量电压_IMM19";
CM_ SG_ 2332111781 M2I_Byrack_Enable_IMM9_21 "绝缘采样使能位_IMM19";
CM_ SG_ 2332111781 M2I_Byrack_ReVeEnable_IMM19_21 "读取软件版本使能位_IMM19";
CM_ SG_ 2332111781 Reserved_21 "预留预留";
CM_ SG_ 2332111781 M2I_Byrack_IsPostTm_IMM19_21 "绝缘采样时间_IMM19";
CM_ SG_ 2332111781 M2I_Byrack_SysABStTm_IMM19_21 "电压稳定时间_IMM19";
CM_ SG_ 2332111782 CRC_M2I_Byrack_IMM19_22 "CRC校验_IMM19";
CM_ SG_ 2332111782 M2I_Byrack_HVS_IMM19_22 "绝缘测量电压_IMM19";
CM_ SG_ 2332111782 M2I_Byrack_Enable_IMM9_22 "绝缘采样使能位_IMM19";
CM_ SG_ 2332111782 M2I_Byrack_ReVeEnable_IMM19_22 "读取软件版本使能位_IMM19";
CM_ SG_ 2332111782 Reserved_22 "预留预留";
CM_ SG_ 2332111782 M2I_Byrack_IsPostTm_IMM19_22 "绝缘采样时间_IMM19";
CM_ SG_ 2332111782 M2I_Byrack_SysABStTm_IMM19_22 "电压稳定时间_IMM19";
CM_ SG_ 2332111783 CRC_M2I_Byrack_IMM19_23 "CRC校验_IMM19";
CM_ SG_ 2332111783 M2I_Byrack_HVS_IMM19_23 "绝缘测量电压_IMM19";
CM_ SG_ 2332111783 M2I_Byrack_Enable_IMM9_23 "绝缘采样使能位_IMM19";
CM_ SG_ 2332111783 M2I_Byrack_ReVeEnable_IMM19_23 "读取软件版本使能位_IMM19";
CM_ SG_ 2332111783 Reserved_23 "预留预留";
CM_ SG_ 2332111783 M2I_Byrack_IsPostTm_IMM19_23 "绝缘采样时间_IMM19";
CM_ SG_ 2332111783 M2I_Byrack_SysABStTm_IMM19_23 "电压稳定时间_IMM19";
CM_ SG_ 2332111784 CRC_M2I_Byrack_IMM19_24 "CRC校验_IMM19";
CM_ SG_ 2332111784 M2I_Byrack_HVS_IMM19_24 "绝缘测量电压_IMM19";
CM_ SG_ 2332111784 M2I_Byrack_Enable_IMM9_24 "绝缘采样使能位_IMM19";
CM_ SG_ 2332111784 M2I_Byrack_ReVeEnable_IMM19_24 "读取软件版本使能位_IMM19";
CM_ SG_ 2332111784 Reserved_24 "预留预留";
CM_ SG_ 2332111784 M2I_Byrack_IsPostTm_IMM19_24 "绝缘采样时间_IMM19";
CM_ SG_ 2332111784 M2I_Byrack_SysABStTm_IMM19_24 "电压稳定时间_IMM19";
CM_ SG_ 2332111785 CRC_M2I_Byrack_IMM19_25 "CRC校验_IMM19";
CM_ SG_ 2332111785 M2I_Byrack_HVS_IMM19_25 "绝缘测量电压_IMM19";
CM_ SG_ 2332111785 M2I_Byrack_Enable_IMM9_25 "绝缘采样使能位_IMM19";
CM_ SG_ 2332111785 M2I_Byrack_ReVeEnable_IMM19_25 "读取软件版本使能位_IMM19";
CM_ SG_ 2332111785 Reserved_25 "预留预留";
CM_ SG_ 2332111785 M2I_Byrack_IsPostTm_IMM19_25 "绝缘采样时间_IMM19";
CM_ SG_ 2332111785 M2I_Byrack_SysABStTm_IMM19_25 "电压稳定时间_IMM19";
CM_ SG_ 2332111786 CRC_M2I_Byrack_IMM19_26 "CRC校验_IMM19";
CM_ SG_ 2332111786 M2I_Byrack_HVS_IMM19_26 "绝缘测量电压_IMM19";
CM_ SG_ 2332111786 M2I_Byrack_Enable_IMM9_26 "绝缘采样使能位_IMM19";
CM_ SG_ 2332111786 M2I_Byrack_ReVeEnable_IMM19_26 "读取软件版本使能位_IMM19";
CM_ SG_ 2332111786 Reserved_26 "预留预留";
CM_ SG_ 2332111786 M2I_Byrack_IsPostTm_IMM19_26 "绝缘采样时间_IMM19";
CM_ SG_ 2332111786 M2I_Byrack_SysABStTm_IMM19_26 "电压稳定时间_IMM19";
CM_ SG_ 2332111787 CRC_M2I_Byrack_IMM19_27 "CRC校验_IMM19";
CM_ SG_ 2332111787 M2I_Byrack_HVS_IMM19_27 "绝缘测量电压_IMM19";
CM_ SG_ 2332111787 M2I_Byrack_Enable_IMM9_27 "绝缘采样使能位_IMM19";
CM_ SG_ 2332111787 M2I_Byrack_ReVeEnable_IMM19_27 "读取软件版本使能位_IMM19";
CM_ SG_ 2332111787 Reserved_27 "预留预留";
CM_ SG_ 2332111787 M2I_Byrack_IsPostTm_IMM19_27 "绝缘采样时间_IMM19";
CM_ SG_ 2332111787 M2I_Byrack_SysABStTm_IMM19_27 "电压稳定时间_IMM19";
CM_ SG_ 2332111788 CRC_M2I_Byrack_IMM19_28 "CRC校验_IMM19";
CM_ SG_ 2332111788 M2I_Byrack_HVS_IMM19_28 "绝缘测量电压_IMM19";
CM_ SG_ 2332111788 M2I_Byrack_Enable_IMM9_28 "绝缘采样使能位_IMM19";
CM_ SG_ 2332111788 M2I_Byrack_ReVeEnable_IMM19_28 "读取软件版本使能位_IMM19";
CM_ SG_ 2332111788 Reserved_28 "预留预留";
CM_ SG_ 2332111788 M2I_Byrack_IsPostTm_IMM19_28 "绝缘采样时间_IMM19";
CM_ SG_ 2332111788 M2I_Byrack_SysABStTm_IMM19_28 "电压稳定时间_IMM19";
CM_ SG_ 2332111789 CRC_M2I_Byrack_IMM19_29 "CRC校验_IMM19";
CM_ SG_ 2332111789 M2I_Byrack_HVS_IMM19_29 "绝缘测量电压_IMM19";
CM_ SG_ 2332111789 M2I_Byrack_Enable_IMM9_29 "绝缘采样使能位_IMM19";
CM_ SG_ 2332111789 M2I_Byrack_ReVeEnable_IMM19_29 "读取软件版本使能位_IMM19";
CM_ SG_ 2332111789 Reserved_29 "预留预留";
CM_ SG_ 2332111789 M2I_Byrack_IsPostTm_IMM19_29 "绝缘采样时间_IMM19";
CM_ SG_ 2332111789 M2I_Byrack_SysABStTm_IMM19_29 "电压稳定时间_IMM19";
CM_ SG_ 2332111790 CRC_M2I_Byrack_IMM19_30 "CRC校验_IMM19";
CM_ SG_ 2332111790 M2I_Byrack_HVS_IMM19_30 "绝缘测量电压_IMM19";
CM_ SG_ 2332111790 M2I_Byrack_Enable_IMM9_30 "绝缘采样使能位_IMM19";
CM_ SG_ 2332111790 M2I_Byrack_ReVeEnable_IMM19_30 "读取软件版本使能位_IMM19";
CM_ SG_ 2332111790 Reserved_30 "预留预留";
CM_ SG_ 2332111790 M2I_Byrack_IsPostTm_IMM19_30 "绝缘采样时间_IMM19";
CM_ SG_ 2332111790 M2I_Byrack_SysABStTm_IMM19_30 "电压稳定时间_IMM19";
CM_ SG_ 2332111791 CRC_M2I_Byrack_IMM19_31 "CRC校验_IMM19";
CM_ SG_ 2332111791 M2I_Byrack_HVS_IMM19_31 "绝缘测量电压_IMM19";
CM_ SG_ 2332111791 M2I_Byrack_Enable_IMM9_31 "绝缘采样使能位_IMM19";
CM_ SG_ 2332111791 M2I_Byrack_ReVeEnable_IMM19_31 "读取软件版本使能位_IMM19";
CM_ SG_ 2332111791 Reserved_31 "预留预留";
CM_ SG_ 2332111791 M2I_Byrack_IsPostTm_IMM19_31 "绝缘采样时间_IMM19";
CM_ SG_ 2332111791 M2I_Byrack_SysABStTm_IMM19_31 "电压稳定时间_IMM19";
CM_ SG_ 2332112017 CRC_M2I_Byrack_IMM20_01 "CRC校验_IMM20";
CM_ SG_ 2332112017 M2I_Byrack_HVS_IMM20_01 "绝缘测量电压_IMM20";
CM_ SG_ 2332112017 M2I_Byrack_Enable_IMM20_01 "绝缘采样使能位_IMM20";
CM_ SG_ 2332112017 M2I_Byrack_ReVeEnable_IMM20_01 "读取软件版本使能位_IMM20";
CM_ SG_ 2332112017 Reserved_01 "预留预留";
CM_ SG_ 2332112017 M2I_Byrack_IsPostTm_IMM20_01 "绝缘采样时间_IMM20";
CM_ SG_ 2332112017 M2I_Byrack_SysABStTm_IMM20_01 "电压稳定时间_IMM20";
CM_ SG_ 2332112018 CRC_M2I_Byrack_IMM20_02 "CRC校验_IMM20";
CM_ SG_ 2332112018 M2I_Byrack_HVS_IMM20_02 "绝缘测量电压_IMM20";
CM_ SG_ 2332112018 M2I_Byrack_Enable_IMM20_02 "绝缘采样使能位_IMM20";
CM_ SG_ 2332112018 M2I_Byrack_ReVeEnable_IMM20_02 "读取软件版本使能位_IMM20";
CM_ SG_ 2332112018 Reserved_02 "预留预留";
CM_ SG_ 2332112018 M2I_Byrack_IsPostTm_IMM20_02 "绝缘采样时间_IMM20";
CM_ SG_ 2332112018 M2I_Byrack_SysABStTm_IMM20_02 "电压稳定时间_IMM20";
CM_ SG_ 2332112019 CRC_M2I_Byrack_IMM20_03 "CRC校验_IMM20";
CM_ SG_ 2332112019 M2I_Byrack_HVS_IMM20_03 "绝缘测量电压_IMM20";
CM_ SG_ 2332112019 M2I_Byrack_Enable_IMM20_03 "绝缘采样使能位_IMM20";
CM_ SG_ 2332112019 M2I_Byrack_ReVeEnable_IMM20_03 "读取软件版本使能位_IMM20";
CM_ SG_ 2332112019 Reserved_03 "预留预留";
CM_ SG_ 2332112019 M2I_Byrack_IsPostTm_IMM20_03 "绝缘采样时间_IMM20";
CM_ SG_ 2332112019 M2I_Byrack_SysABStTm_IMM20_03 "电压稳定时间_IMM20";
CM_ SG_ 2332112020 CRC_M2I_Byrack_IMM20_04 "CRC校验_IMM20";
CM_ SG_ 2332112020 M2I_Byrack_HVS_IMM20_04 "绝缘测量电压_IMM20";
CM_ SG_ 2332112020 M2I_Byrack_Enable_IMM20_04 "绝缘采样使能位_IMM20";
CM_ SG_ 2332112020 M2I_Byrack_ReVeEnable_IMM20_04 "读取软件版本使能位_IMM20";
CM_ SG_ 2332112020 Reserved_04 "预留预留";
CM_ SG_ 2332112020 M2I_Byrack_IsPostTm_IMM20_04 "绝缘采样时间_IMM20";
CM_ SG_ 2332112020 M2I_Byrack_SysABStTm_IMM20_04 "电压稳定时间_IMM20";
CM_ SG_ 2332112021 CRC_M2I_Byrack_IMM20_05 "CRC校验_IMM20";
CM_ SG_ 2332112021 M2I_Byrack_HVS_IMM20_05 "绝缘测量电压_IMM20";
CM_ SG_ 2332112021 M2I_Byrack_Enable_IMM20_05 "绝缘采样使能位_IMM20";
CM_ SG_ 2332112021 M2I_Byrack_ReVeEnable_IMM20_05 "读取软件版本使能位_IMM20";
CM_ SG_ 2332112021 Reserved_05 "预留预留";
CM_ SG_ 2332112021 M2I_Byrack_IsPostTm_IMM20_05 "绝缘采样时间_IMM20";
CM_ SG_ 2332112021 M2I_Byrack_SysABStTm_IMM20_05 "电压稳定时间_IMM20";
CM_ SG_ 2332112022 CRC_M2I_Byrack_IMM20_06 "CRC校验_IMM20";
CM_ SG_ 2332112022 M2I_Byrack_HVS_IMM20_06 "绝缘测量电压_IMM20";
CM_ SG_ 2332112022 M2I_Byrack_Enable_IMM20_06 "绝缘采样使能位_IMM20";
CM_ SG_ 2332112022 M2I_Byrack_ReVeEnable_IMM20_06 "读取软件版本使能位_IMM20";
CM_ SG_ 2332112022 Reserved_06 "预留预留";
CM_ SG_ 2332112022 M2I_Byrack_IsPostTm_IMM20_06 "绝缘采样时间_IMM20";
CM_ SG_ 2332112022 M2I_Byrack_SysABStTm_IMM20_06 "电压稳定时间_IMM20";
CM_ SG_ 2332112023 CRC_M2I_Byrack_IMM20_07 "CRC校验_IMM20";
CM_ SG_ 2332112023 M2I_Byrack_HVS_IMM20_07 "绝缘测量电压_IMM20";
CM_ SG_ 2332112023 M2I_Byrack_Enable_IMM20_07 "绝缘采样使能位_IMM20";
CM_ SG_ 2332112023 M2I_Byrack_ReVeEnable_IMM20_07 "读取软件版本使能位_IMM20";
CM_ SG_ 2332112023 Reserved_07 "预留预留";
CM_ SG_ 2332112023 M2I_Byrack_IsPostTm_IMM20_07 "绝缘采样时间_IMM20";
CM_ SG_ 2332112023 M2I_Byrack_SysABStTm_IMM20_07 "电压稳定时间_IMM20";
CM_ SG_ 2332112024 CRC_M2I_Byrack_IMM20_08 "CRC校验_IMM20";
CM_ SG_ 2332112024 M2I_Byrack_HVS_IMM20_08 "绝缘测量电压_IMM20";
CM_ SG_ 2332112024 M2I_Byrack_Enable_IMM20_08 "绝缘采样使能位_IMM20";
CM_ SG_ 2332112024 M2I_Byrack_ReVeEnable_IMM20_08 "读取软件版本使能位_IMM20";
CM_ SG_ 2332112024 Reserved_08 "预留预留";
CM_ SG_ 2332112024 M2I_Byrack_IsPostTm_IMM20_08 "绝缘采样时间_IMM20";
CM_ SG_ 2332112024 M2I_Byrack_SysABStTm_IMM20_08 "电压稳定时间_IMM20";
CM_ SG_ 2332112025 CRC_M2I_Byrack_IMM20_09 "CRC校验_IMM20";
CM_ SG_ 2332112025 M2I_Byrack_HVS_IMM20_09 "绝缘测量电压_IMM20";
CM_ SG_ 2332112025 M2I_Byrack_Enable_IMM20_09 "绝缘采样使能位_IMM20";
CM_ SG_ 2332112025 M2I_Byrack_ReVeEnable_IMM20_09 "读取软件版本使能位_IMM20";
CM_ SG_ 2332112025 Reserved_09 "预留预留";
CM_ SG_ 2332112025 M2I_Byrack_IsPostTm_IMM20_09 "绝缘采样时间_IMM20";
CM_ SG_ 2332112025 M2I_Byrack_SysABStTm_IMM20_09 "电压稳定时间_IMM20";
CM_ SG_ 2332112026 CRC_M2I_Byrack_IMM20_10 "CRC校验_IMM20";
CM_ SG_ 2332112026 M2I_Byrack_HVS_IMM20_10 "绝缘测量电压_IMM20";
CM_ SG_ 2332112026 M2I_Byrack_Enable_IMM20_10 "绝缘采样使能位_IMM20";
CM_ SG_ 2332112026 M2I_Byrack_ReVeEnable_IMM20_10 "读取软件版本使能位_IMM20";
CM_ SG_ 2332112026 Reserved_10 "预留预留";
CM_ SG_ 2332112026 M2I_Byrack_IsPostTm_IMM20_10 "绝缘采样时间_IMM20";
CM_ SG_ 2332112026 M2I_Byrack_SysABStTm_IMM20_10 "电压稳定时间_IMM20";
CM_ SG_ 2332112027 CRC_M2I_Byrack_IMM20_11 "CRC校验_IMM20";
CM_ SG_ 2332112027 M2I_Byrack_HVS_IMM20_11 "绝缘测量电压_IMM20";
CM_ SG_ 2332112027 M2I_Byrack_Enable_IMM20_11 "绝缘采样使能位_IMM20";
CM_ SG_ 2332112027 M2I_Byrack_ReVeEnable_IMM20_11 "读取软件版本使能位_IMM20";
CM_ SG_ 2332112027 Reserved_11 "预留预留";
CM_ SG_ 2332112027 M2I_Byrack_IsPostTm_IMM20_11 "绝缘采样时间_IMM20";
CM_ SG_ 2332112027 M2I_Byrack_SysABStTm_IMM20_11 "电压稳定时间_IMM20";
CM_ SG_ 2332112028 CRC_M2I_Byrack_IMM20_12 "CRC校验_IMM20";
CM_ SG_ 2332112028 M2I_Byrack_HVS_IMM20_12 "绝缘测量电压_IMM20";
CM_ SG_ 2332112028 M2I_Byrack_Enable_IMM20_12 "绝缘采样使能位_IMM20";
CM_ SG_ 2332112028 M2I_Byrack_ReVeEnable_IMM20_12 "读取软件版本使能位_IMM20";
CM_ SG_ 2332112028 Reserved_12 "预留预留";
CM_ SG_ 2332112028 M2I_Byrack_IsPostTm_IMM20_12 "绝缘采样时间_IMM20";
CM_ SG_ 2332112028 M2I_Byrack_SysABStTm_IMM20_12 "电压稳定时间_IMM20";
CM_ SG_ 2332112029 CRC_M2I_Byrack_IMM20_13 "CRC校验_IMM20";
CM_ SG_ 2332112029 M2I_Byrack_HVS_IMM20_13 "绝缘测量电压_IMM20";
CM_ SG_ 2332112029 M2I_Byrack_Enable_IMM20_13 "绝缘采样使能位_IMM20";
CM_ SG_ 2332112029 M2I_Byrack_ReVeEnable_IMM20_13 "读取软件版本使能位_IMM20";
CM_ SG_ 2332112029 Reserved_13 "预留预留";
CM_ SG_ 2332112029 M2I_Byrack_IsPostTm_IMM20_13 "绝缘采样时间_IMM20";
CM_ SG_ 2332112029 M2I_Byrack_SysABStTm_IMM20_13 "电压稳定时间_IMM20";
CM_ SG_ 2332112030 CRC_M2I_Byrack_IMM20_14 "CRC校验_IMM20";
CM_ SG_ 2332112030 M2I_Byrack_HVS_IMM20_14 "绝缘测量电压_IMM20";
CM_ SG_ 2332112030 M2I_Byrack_Enable_IMM20_14 "绝缘采样使能位_IMM20";
CM_ SG_ 2332112030 M2I_Byrack_ReVeEnable_IMM20_14 "读取软件版本使能位_IMM20";
CM_ SG_ 2332112030 Reserved_14 "预留预留";
CM_ SG_ 2332112030 M2I_Byrack_IsPostTm_IMM20_14 "绝缘采样时间_IMM20";
CM_ SG_ 2332112030 M2I_Byrack_SysABStTm_IMM20_14 "电压稳定时间_IMM20";
CM_ SG_ 2332112031 CRC_M2I_Byrack_IMM20_15 "CRC校验_IMM20";
CM_ SG_ 2332112031 M2I_Byrack_HVS_IMM20_15 "绝缘测量电压_IMM20";
CM_ SG_ 2332112031 M2I_Byrack_Enable_IMM20_15 "绝缘采样使能位_IMM20";
CM_ SG_ 2332112031 M2I_Byrack_ReVeEnable_IMM20_15 "读取软件版本使能位_IMM20";
CM_ SG_ 2332112031 Reserved_15 "预留预留";
CM_ SG_ 2332112031 M2I_Byrack_IsPostTm_IMM20_15 "绝缘采样时间_IMM20";
CM_ SG_ 2332112031 M2I_Byrack_SysABStTm_IMM20_15 "电压稳定时间_IMM20";
CM_ SG_ 2332112032 CRC_M2I_Byrack_IMM20_16 "CRC校验_IMM20";
CM_ SG_ 2332112032 M2I_Byrack_HVS_IMM20_16 "绝缘测量电压_IMM20";
CM_ SG_ 2332112032 M2I_Byrack_Enable_IMM20_16 "绝缘采样使能位_IMM20";
CM_ SG_ 2332112032 M2I_Byrack_ReVeEnable_IMM20_16 "读取软件版本使能位_IMM20";
CM_ SG_ 2332112032 Reserved_16 "预留预留";
CM_ SG_ 2332112032 M2I_Byrack_IsPostTm_IMM20_16 "绝缘采样时间_IMM20";
CM_ SG_ 2332112032 M2I_Byrack_SysABStTm_IMM20_16 "电压稳定时间_IMM20";
CM_ SG_ 2332112033 CRC_M2I_Byrack_IMM20_17 "CRC校验_IMM20";
CM_ SG_ 2332112033 M2I_Byrack_HVS_IMM20_17 "绝缘测量电压_IMM20";
CM_ SG_ 2332112033 M2I_Byrack_Enable_IMM20_17 "绝缘采样使能位_IMM20";
CM_ SG_ 2332112033 M2I_Byrack_ReVeEnable_IMM20_17 "读取软件版本使能位_IMM20";
CM_ SG_ 2332112033 Reserved_17 "预留预留";
CM_ SG_ 2332112033 M2I_Byrack_IsPostTm_IMM20_17 "绝缘采样时间_IMM20";
CM_ SG_ 2332112033 M2I_Byrack_SysABStTm_IMM20_17 "电压稳定时间_IMM20";
CM_ SG_ 2332112034 CRC_M2I_Byrack_IMM20_18 "CRC校验_IMM20";
CM_ SG_ 2332112034 M2I_Byrack_HVS_IMM20_18 "绝缘测量电压_IMM20";
CM_ SG_ 2332112034 M2I_Byrack_Enable_IMM20_18 "绝缘采样使能位_IMM20";
CM_ SG_ 2332112034 M2I_Byrack_ReVeEnable_IMM20_18 "读取软件版本使能位_IMM20";
CM_ SG_ 2332112034 Reserved_18 "预留预留";
CM_ SG_ 2332112034 M2I_Byrack_IsPostTm_IMM20_18 "绝缘采样时间_IMM20";
CM_ SG_ 2332112034 M2I_Byrack_SysABStTm_IMM20_18 "电压稳定时间_IMM20";
CM_ SG_ 2332112035 CRC_M2I_Byrack_IMM20_19 "CRC校验_IMM20";
CM_ SG_ 2332112035 M2I_Byrack_HVS_IMM20_19 "绝缘测量电压_IMM20";
CM_ SG_ 2332112035 M2I_Byrack_Enable_IMM20_19 "绝缘采样使能位_IMM20";
CM_ SG_ 2332112035 M2I_Byrack_ReVeEnable_IMM20_19 "读取软件版本使能位_IMM20";
CM_ SG_ 2332112035 Reserved_19 "预留预留";
CM_ SG_ 2332112035 M2I_Byrack_IsPostTm_IMM20_19 "绝缘采样时间_IMM20";
CM_ SG_ 2332112035 M2I_Byrack_SysABStTm_IMM20_19 "电压稳定时间_IMM20";
CM_ SG_ 2332112036 CRC_M2I_Byrack_IMM20_20 "CRC校验_IMM20";
CM_ SG_ 2332112036 M2I_Byrack_HVS_IMM20_20 "绝缘测量电压_IMM20";
CM_ SG_ 2332112036 M2I_Byrack_Enable_IMM20_20 "绝缘采样使能位_IMM20";
CM_ SG_ 2332112036 M2I_Byrack_ReVeEnable_IMM20_20 "读取软件版本使能位_IMM20";
CM_ SG_ 2332112036 Reserved_20 "预留预留";
CM_ SG_ 2332112036 M2I_Byrack_IsPostTm_IMM20_20 "绝缘采样时间_IMM20";
CM_ SG_ 2332112036 M2I_Byrack_SysABStTm_IMM20_20 "电压稳定时间_IMM20";
CM_ SG_ 2332112037 CRC_M2I_Byrack_IMM20_21 "CRC校验_IMM20";
CM_ SG_ 2332112037 M2I_Byrack_HVS_IMM20_21 "绝缘测量电压_IMM20";
CM_ SG_ 2332112037 M2I_Byrack_Enable_IMM20_21 "绝缘采样使能位_IMM20";
CM_ SG_ 2332112037 M2I_Byrack_ReVeEnable_IMM20_21 "读取软件版本使能位_IMM20";
CM_ SG_ 2332112037 Reserved_21 "预留预留";
CM_ SG_ 2332112037 M2I_Byrack_IsPostTm_IMM20_21 "绝缘采样时间_IMM20";
CM_ SG_ 2332112037 M2I_Byrack_SysABStTm_IMM20_21 "电压稳定时间_IMM20";
CM_ SG_ 2332112038 CRC_M2I_Byrack_IMM20_22 "CRC校验_IMM20";
CM_ SG_ 2332112038 M2I_Byrack_HVS_IMM20_22 "绝缘测量电压_IMM20";
CM_ SG_ 2332112038 M2I_Byrack_Enable_IMM20_22 "绝缘采样使能位_IMM20";
CM_ SG_ 2332112038 M2I_Byrack_ReVeEnable_IMM20_22 "读取软件版本使能位_IMM20";
CM_ SG_ 2332112038 Reserved_22 "预留预留";
CM_ SG_ 2332112038 M2I_Byrack_IsPostTm_IMM20_22 "绝缘采样时间_IMM20";
CM_ SG_ 2332112038 M2I_Byrack_SysABStTm_IMM20_22 "电压稳定时间_IMM20";
CM_ SG_ 2332112039 CRC_M2I_Byrack_IMM20_23 "CRC校验_IMM20";
CM_ SG_ 2332112039 M2I_Byrack_HVS_IMM20_23 "绝缘测量电压_IMM20";
CM_ SG_ 2332112039 M2I_Byrack_Enable_IMM20_23 "绝缘采样使能位_IMM20";
CM_ SG_ 2332112039 M2I_Byrack_ReVeEnable_IMM20_23 "读取软件版本使能位_IMM20";
CM_ SG_ 2332112039 Reserved_23 "预留预留";
CM_ SG_ 2332112039 M2I_Byrack_IsPostTm_IMM20_23 "绝缘采样时间_IMM20";
CM_ SG_ 2332112039 M2I_Byrack_SysABStTm_IMM20_23 "电压稳定时间_IMM20";
CM_ SG_ 2332112040 CRC_M2I_Byrack_IMM20_24 "CRC校验_IMM20";
CM_ SG_ 2332112040 M2I_Byrack_HVS_IMM20_24 "绝缘测量电压_IMM20";
CM_ SG_ 2332112040 M2I_Byrack_Enable_IMM20_24 "绝缘采样使能位_IMM20";
CM_ SG_ 2332112040 M2I_Byrack_ReVeEnable_IMM20_24 "读取软件版本使能位_IMM20";
CM_ SG_ 2332112040 Reserved_24 "预留预留";
CM_ SG_ 2332112040 M2I_Byrack_IsPostTm_IMM20_24 "绝缘采样时间_IMM20";
CM_ SG_ 2332112040 M2I_Byrack_SysABStTm_IMM20_24 "电压稳定时间_IMM20";
CM_ SG_ 2332112041 CRC_M2I_Byrack_IMM20_25 "CRC校验_IMM20";
CM_ SG_ 2332112041 M2I_Byrack_HVS_IMM20_25 "绝缘测量电压_IMM20";
CM_ SG_ 2332112041 M2I_Byrack_Enable_IMM20_25 "绝缘采样使能位_IMM20";
CM_ SG_ 2332112041 M2I_Byrack_ReVeEnable_IMM20_25 "读取软件版本使能位_IMM20";
CM_ SG_ 2332112041 Reserved_25 "预留预留";
CM_ SG_ 2332112041 M2I_Byrack_IsPostTm_IMM20_25 "绝缘采样时间_IMM20";
CM_ SG_ 2332112041 M2I_Byrack_SysABStTm_IMM20_25 "电压稳定时间_IMM20";
CM_ SG_ 2332112042 CRC_M2I_Byrack_IMM20_26 "CRC校验_IMM20";
CM_ SG_ 2332112042 M2I_Byrack_HVS_IMM20_26 "绝缘测量电压_IMM20";
CM_ SG_ 2332112042 M2I_Byrack_Enable_IMM20_26 "绝缘采样使能位_IMM20";
CM_ SG_ 2332112042 M2I_Byrack_ReVeEnable_IMM20_26 "读取软件版本使能位_IMM20";
CM_ SG_ 2332112042 Reserved_26 "预留预留";
CM_ SG_ 2332112042 M2I_Byrack_IsPostTm_IMM20_26 "绝缘采样时间_IMM20";
CM_ SG_ 2332112042 M2I_Byrack_SysABStTm_IMM20_26 "电压稳定时间_IMM20";
CM_ SG_ 2332112043 CRC_M2I_Byrack_IMM20_27 "CRC校验_IMM20";
CM_ SG_ 2332112043 M2I_Byrack_HVS_IMM20_27 "绝缘测量电压_IMM20";
CM_ SG_ 2332112043 M2I_Byrack_Enable_IMM20_27 "绝缘采样使能位_IMM20";
CM_ SG_ 2332112043 M2I_Byrack_ReVeEnable_IMM20_27 "读取软件版本使能位_IMM20";
CM_ SG_ 2332112043 Reserved_27 "预留预留";
CM_ SG_ 2332112043 M2I_Byrack_IsPostTm_IMM20_27 "绝缘采样时间_IMM20";
CM_ SG_ 2332112043 M2I_Byrack_SysABStTm_IMM20_27 "电压稳定时间_IMM20";
CM_ SG_ 2332112044 CRC_M2I_Byrack_IMM20_28 "CRC校验_IMM20";
CM_ SG_ 2332112044 M2I_Byrack_HVS_IMM20_28 "绝缘测量电压_IMM20";
CM_ SG_ 2332112044 M2I_Byrack_Enable_IMM20_28 "绝缘采样使能位_IMM20";
CM_ SG_ 2332112044 M2I_Byrack_ReVeEnable_IMM20_28 "读取软件版本使能位_IMM20";
CM_ SG_ 2332112044 Reserved_28 "预留预留";
CM_ SG_ 2332112044 M2I_Byrack_IsPostTm_IMM20_28 "绝缘采样时间_IMM20";
CM_ SG_ 2332112044 M2I_Byrack_SysABStTm_IMM20_28 "电压稳定时间_IMM20";
CM_ SG_ 2332112045 CRC_M2I_Byrack_IMM20_29 "CRC校验_IMM20";
CM_ SG_ 2332112045 M2I_Byrack_HVS_IMM20_29 "绝缘测量电压_IMM20";
CM_ SG_ 2332112045 M2I_Byrack_Enable_IMM20_29 "绝缘采样使能位_IMM20";
CM_ SG_ 2332112045 M2I_Byrack_ReVeEnable_IMM20_29 "读取软件版本使能位_IMM20";
CM_ SG_ 2332112045 Reserved_29 "预留预留";
CM_ SG_ 2332112045 M2I_Byrack_IsPostTm_IMM20_29 "绝缘采样时间_IMM20";
CM_ SG_ 2332112045 M2I_Byrack_SysABStTm_IMM20_29 "电压稳定时间_IMM20";
CM_ SG_ 2332112046 CRC_M2I_Byrack_IMM20_30 "CRC校验_IMM20";
CM_ SG_ 2332112046 M2I_Byrack_HVS_IMM20_30 "绝缘测量电压_IMM20";
CM_ SG_ 2332112046 M2I_Byrack_Enable_IMM20_30 "绝缘采样使能位_IMM20";
CM_ SG_ 2332112046 M2I_Byrack_ReVeEnable_IMM20_30 "读取软件版本使能位_IMM20";
CM_ SG_ 2332112046 Reserved_30 "预留预留";
CM_ SG_ 2332112046 M2I_Byrack_IsPostTm_IMM20_30 "绝缘采样时间_IMM20";
CM_ SG_ 2332112046 M2I_Byrack_SysABStTm_IMM20_30 "电压稳定时间_IMM20";
CM_ SG_ 2332112047 CRC_M2I_Byrack_IMM20_31 "CRC校验_IMM20";
CM_ SG_ 2332112047 M2I_Byrack_HVS_IMM20_31 "绝缘测量电压_IMM20";
CM_ SG_ 2332112047 M2I_Byrack_Enable_IMM20_31 "绝缘采样使能位_IMM20";
CM_ SG_ 2332112047 M2I_Byrack_ReVeEnable_IMM20_31 "读取软件版本使能位_IMM20";
CM_ SG_ 2332112047 Reserved_31 "预留预留";
CM_ SG_ 2332112047 M2I_Byrack_IsPostTm_IMM20_31 "绝缘采样时间_IMM20";
CM_ SG_ 2332112047 M2I_Byrack_SysABStTm_IMM20_31 "电压稳定时间_IMM20";
CM_ SG_ 2332112273 CRC_M2I_Byrack_IMM21_01 "CRC校验_IMM21";
CM_ SG_ 2332112273 M2I_Byrack_HVS_IMM21_01 "绝缘测量电压_IMM21";
CM_ SG_ 2332112273 M2I_Byrack_Enable_IMM21_01 "绝缘采样使能位_IMM21";
CM_ SG_ 2332112273 M2I_Byrack_ReVeEnable_IMM21_01 "读取软件版本使能位_IMM21";
CM_ SG_ 2332112273 Reserved_01 "预留预留";
CM_ SG_ 2332112273 M2I_Byrack_IsPostTm_IMM21_01 "绝缘采样时间_IMM21";
CM_ SG_ 2332112273 M2I_Byrack_SysABStTm_IMM21_01 "电压稳定时间_IMM21";
CM_ SG_ 2332112274 CRC_M2I_Byrack_IMM21_02 "CRC校验_IMM21";
CM_ SG_ 2332112274 M2I_Byrack_HVS_IMM21_02 "绝缘测量电压_IMM21";
CM_ SG_ 2332112274 M2I_Byrack_Enable_IMM21_02 "绝缘采样使能位_IMM21";
CM_ SG_ 2332112274 M2I_Byrack_ReVeEnable_IMM21_02 "读取软件版本使能位_IMM21";
CM_ SG_ 2332112274 Reserved_02 "预留预留";
CM_ SG_ 2332112274 M2I_Byrack_IsPostTm_IMM21_02 "绝缘采样时间_IMM21";
CM_ SG_ 2332112274 M2I_Byrack_SysABStTm_IMM21_02 "电压稳定时间_IMM21";
CM_ SG_ 2332112275 CRC_M2I_Byrack_IMM21_03 "CRC校验_IMM21";
CM_ SG_ 2332112275 M2I_Byrack_HVS_IMM21_03 "绝缘测量电压_IMM21";
CM_ SG_ 2332112275 M2I_Byrack_Enable_IMM21_03 "绝缘采样使能位_IMM21";
CM_ SG_ 2332112275 M2I_Byrack_ReVeEnable_IMM21_03 "读取软件版本使能位_IMM21";
CM_ SG_ 2332112275 Reserved_03 "预留预留";
CM_ SG_ 2332112275 M2I_Byrack_IsPostTm_IMM21_03 "绝缘采样时间_IMM21";
CM_ SG_ 2332112275 M2I_Byrack_SysABStTm_IMM21_03 "电压稳定时间_IMM21";
CM_ SG_ 2332112276 CRC_M2I_Byrack_IMM21_04 "CRC校验_IMM21";
CM_ SG_ 2332112276 M2I_Byrack_HVS_IMM21_04 "绝缘测量电压_IMM21";
CM_ SG_ 2332112276 M2I_Byrack_Enable_IMM21_04 "绝缘采样使能位_IMM21";
CM_ SG_ 2332112276 M2I_Byrack_ReVeEnable_IMM21_04 "读取软件版本使能位_IMM21";
CM_ SG_ 2332112276 Reserved_04 "预留预留";
CM_ SG_ 2332112276 M2I_Byrack_IsPostTm_IMM21_04 "绝缘采样时间_IMM21";
CM_ SG_ 2332112276 M2I_Byrack_SysABStTm_IMM21_04 "电压稳定时间_IMM21";
CM_ SG_ 2332112277 CRC_M2I_Byrack_IMM21_05 "CRC校验_IMM21";
CM_ SG_ 2332112277 M2I_Byrack_HVS_IMM21_05 "绝缘测量电压_IMM21";
CM_ SG_ 2332112277 M2I_Byrack_Enable_IMM21_05 "绝缘采样使能位_IMM21";
CM_ SG_ 2332112277 M2I_Byrack_ReVeEnable_IMM21_05 "读取软件版本使能位_IMM21";
CM_ SG_ 2332112277 Reserved_05 "预留预留";
CM_ SG_ 2332112277 M2I_Byrack_IsPostTm_IMM21_05 "绝缘采样时间_IMM21";
CM_ SG_ 2332112277 M2I_Byrack_SysABStTm_IMM21_05 "电压稳定时间_IMM21";
CM_ SG_ 2332112278 CRC_M2I_Byrack_IMM21_06 "CRC校验_IMM21";
CM_ SG_ 2332112278 M2I_Byrack_HVS_IMM21_06 "绝缘测量电压_IMM21";
CM_ SG_ 2332112278 M2I_Byrack_Enable_IMM21_06 "绝缘采样使能位_IMM21";
CM_ SG_ 2332112278 M2I_Byrack_ReVeEnable_IMM21_06 "读取软件版本使能位_IMM21";
CM_ SG_ 2332112278 Reserved_06 "预留预留";
CM_ SG_ 2332112278 M2I_Byrack_IsPostTm_IMM21_06 "绝缘采样时间_IMM21";
CM_ SG_ 2332112278 M2I_Byrack_SysABStTm_IMM21_06 "电压稳定时间_IMM21";
CM_ SG_ 2332112279 CRC_M2I_Byrack_IMM21_07 "CRC校验_IMM21";
CM_ SG_ 2332112279 M2I_Byrack_HVS_IMM21_07 "绝缘测量电压_IMM21";
CM_ SG_ 2332112279 M2I_Byrack_Enable_IMM21_07 "绝缘采样使能位_IMM21";
CM_ SG_ 2332112279 M2I_Byrack_ReVeEnable_IMM21_07 "读取软件版本使能位_IMM21";
CM_ SG_ 2332112279 Reserved_07 "预留预留";
CM_ SG_ 2332112279 M2I_Byrack_IsPostTm_IMM21_07 "绝缘采样时间_IMM21";
CM_ SG_ 2332112279 M2I_Byrack_SysABStTm_IMM21_07 "电压稳定时间_IMM21";
CM_ SG_ 2332112280 CRC_M2I_Byrack_IMM21_08 "CRC校验_IMM21";
CM_ SG_ 2332112280 M2I_Byrack_HVS_IMM21_08 "绝缘测量电压_IMM21";
CM_ SG_ 2332112280 M2I_Byrack_Enable_IMM21_08 "绝缘采样使能位_IMM21";
CM_ SG_ 2332112280 M2I_Byrack_ReVeEnable_IMM21_08 "读取软件版本使能位_IMM21";
CM_ SG_ 2332112280 Reserved_08 "预留预留";
CM_ SG_ 2332112280 M2I_Byrack_IsPostTm_IMM21_08 "绝缘采样时间_IMM21";
CM_ SG_ 2332112280 M2I_Byrack_SysABStTm_IMM21_08 "电压稳定时间_IMM21";
CM_ SG_ 2332112281 CRC_M2I_Byrack_IMM21_09 "CRC校验_IMM21";
CM_ SG_ 2332112281 M2I_Byrack_HVS_IMM21_09 "绝缘测量电压_IMM21";
CM_ SG_ 2332112281 M2I_Byrack_Enable_IMM21_09 "绝缘采样使能位_IMM21";
CM_ SG_ 2332112281 M2I_Byrack_ReVeEnable_IMM21_09 "读取软件版本使能位_IMM21";
CM_ SG_ 2332112281 Reserved_09 "预留预留";
CM_ SG_ 2332112281 M2I_Byrack_IsPostTm_IMM21_09 "绝缘采样时间_IMM21";
CM_ SG_ 2332112281 M2I_Byrack_SysABStTm_IMM21_09 "电压稳定时间_IMM21";
CM_ SG_ 2332112282 CRC_M2I_Byrack_IMM21_10 "CRC校验_IMM21";
CM_ SG_ 2332112282 M2I_Byrack_HVS_IMM21_10 "绝缘测量电压_IMM21";
CM_ SG_ 2332112282 M2I_Byrack_Enable_IMM21_10 "绝缘采样使能位_IMM21";
CM_ SG_ 2332112282 M2I_Byrack_ReVeEnable_IMM21_10 "读取软件版本使能位_IMM21";
CM_ SG_ 2332112282 Reserved_10 "预留预留";
CM_ SG_ 2332112282 M2I_Byrack_IsPostTm_IMM21_10 "绝缘采样时间_IMM21";
CM_ SG_ 2332112282 M2I_Byrack_SysABStTm_IMM21_10 "电压稳定时间_IMM21";
CM_ SG_ 2332112283 CRC_M2I_Byrack_IMM21_11 "CRC校验_IMM21";
CM_ SG_ 2332112283 M2I_Byrack_HVS_IMM21_11 "绝缘测量电压_IMM21";
CM_ SG_ 2332112283 M2I_Byrack_Enable_IMM21_11 "绝缘采样使能位_IMM21";
CM_ SG_ 2332112283 M2I_Byrack_ReVeEnable_IMM21_11 "读取软件版本使能位_IMM21";
CM_ SG_ 2332112283 Reserved_11 "预留预留";
CM_ SG_ 2332112283 M2I_Byrack_IsPostTm_IMM21_11 "绝缘采样时间_IMM21";
CM_ SG_ 2332112283 M2I_Byrack_SysABStTm_IMM21_11 "电压稳定时间_IMM21";
CM_ SG_ 2332112284 CRC_M2I_Byrack_IMM21_12 "CRC校验_IMM21";
CM_ SG_ 2332112284 M2I_Byrack_HVS_IMM21_12 "绝缘测量电压_IMM21";
CM_ SG_ 2332112284 M2I_Byrack_Enable_IMM21_12 "绝缘采样使能位_IMM21";
CM_ SG_ 2332112284 M2I_Byrack_ReVeEnable_IMM21_12 "读取软件版本使能位_IMM21";
CM_ SG_ 2332112284 Reserved_12 "预留预留";
CM_ SG_ 2332112284 M2I_Byrack_IsPostTm_IMM21_12 "绝缘采样时间_IMM21";
CM_ SG_ 2332112284 M2I_Byrack_SysABStTm_IMM21_12 "电压稳定时间_IMM21";
CM_ SG_ 2332112285 CRC_M2I_Byrack_IMM21_13 "CRC校验_IMM21";
CM_ SG_ 2332112285 M2I_Byrack_HVS_IMM21_13 "绝缘测量电压_IMM21";
CM_ SG_ 2332112285 M2I_Byrack_Enable_IMM21_13 "绝缘采样使能位_IMM21";
CM_ SG_ 2332112285 M2I_Byrack_ReVeEnable_IMM21_13 "读取软件版本使能位_IMM21";
CM_ SG_ 2332112285 Reserved_13 "预留预留";
CM_ SG_ 2332112285 M2I_Byrack_IsPostTm_IMM21_13 "绝缘采样时间_IMM21";
CM_ SG_ 2332112285 M2I_Byrack_SysABStTm_IMM21_13 "电压稳定时间_IMM21";
CM_ SG_ 2332112286 CRC_M2I_Byrack_IMM21_14 "CRC校验_IMM21";
CM_ SG_ 2332112286 M2I_Byrack_HVS_IMM21_14 "绝缘测量电压_IMM21";
CM_ SG_ 2332112286 M2I_Byrack_Enable_IMM21_14 "绝缘采样使能位_IMM21";
CM_ SG_ 2332112286 M2I_Byrack_ReVeEnable_IMM21_14 "读取软件版本使能位_IMM21";
CM_ SG_ 2332112286 Reserved_14 "预留预留";
CM_ SG_ 2332112286 M2I_Byrack_IsPostTm_IMM21_14 "绝缘采样时间_IMM21";
CM_ SG_ 2332112286 M2I_Byrack_SysABStTm_IMM21_14 "电压稳定时间_IMM21";
CM_ SG_ 2332112287 CRC_M2I_Byrack_IMM21_15 "CRC校验_IMM21";
CM_ SG_ 2332112287 M2I_Byrack_HVS_IMM21_15 "绝缘测量电压_IMM21";
CM_ SG_ 2332112287 M2I_Byrack_Enable_IMM21_15 "绝缘采样使能位_IMM21";
CM_ SG_ 2332112287 M2I_Byrack_ReVeEnable_IMM21_15 "读取软件版本使能位_IMM21";
CM_ SG_ 2332112287 Reserved_15 "预留预留";
CM_ SG_ 2332112287 M2I_Byrack_IsPostTm_IMM21_15 "绝缘采样时间_IMM21";
CM_ SG_ 2332112287 M2I_Byrack_SysABStTm_IMM21_15 "电压稳定时间_IMM21";
CM_ SG_ 2332112288 CRC_M2I_Byrack_IMM21_16 "CRC校验_IMM21";
CM_ SG_ 2332112288 M2I_Byrack_HVS_IMM21_16 "绝缘测量电压_IMM21";
CM_ SG_ 2332112288 M2I_Byrack_Enable_IMM21_16 "绝缘采样使能位_IMM21";
CM_ SG_ 2332112288 M2I_Byrack_ReVeEnable_IMM21_16 "读取软件版本使能位_IMM21";
CM_ SG_ 2332112288 Reserved_16 "预留预留";
CM_ SG_ 2332112288 M2I_Byrack_IsPostTm_IMM21_16 "绝缘采样时间_IMM21";
CM_ SG_ 2332112288 M2I_Byrack_SysABStTm_IMM21_16 "电压稳定时间_IMM21";
VAL_ 2332110999 M2I_Byrack_Enable_IMM16_07 1 "Deactive" 2 "Active" ;
VAL_ 2332110999 M2I_Byrack_ReVeEnable_IMM16_07 0 "invalid" 1 "Read SW-Version" 2 "Read HW-Version" 3 "Barcode" ;
VAL_ 2332111000 M2I_Byrack_Enable_IMM16_08 1 "Deactive" 2 "Active" ;
VAL_ 2332111000 M2I_Byrack_ReVeEnable_IMM16_08 0 "invalid" 1 "Read SW-Version" 2 "Read HW-Version" 3 "Barcode" ;
VAL_ 2332111001 M2I_Byrack_Enable_IMM16_09 1 "Deactive" 2 "Active" ;
VAL_ 2332111001 M2I_Byrack_ReVeEnable_IMM16_09 0 "invalid" 1 "Read SW-Version" 2 "Read HW-Version" 3 "Barcode" ;
VAL_ 2332111002 M2I_Byrack_Enable_IMM16_10 1 "Deactive" 2 "Active" ;
VAL_ 2332111002 M2I_Byrack_ReVeEnable_IMM16_10 0 "invalid" 1 "Read SW-Version" 2 "Read HW-Version" 3 "Barcode" ;
VAL_ 2332111003 M2I_Byrack_Enable_IMM16_11 1 "Deactive" 2 "Active" ;
VAL_ 2332111003 M2I_Byrack_ReVeEnable_IMM16_11 0 "invalid" 1 "Read SW-Version" 2 "Read HW-Version" 3 "Barcode" ;
VAL_ 2332111004 M2I_Byrack_Enable_IMM16_12 1 "Deactive" 2 "Active" ;
VAL_ 2332111004 M2I_Byrack_ReVeEnable_IMM16_12 0 "invalid" 1 "Read SW-Version" 2 "Read HW-Version" 3 "Barcode" ;
VAL_ 2332111005 M2I_Byrack_Enable_IMM16_13 1 "Deactive" 2 "Active" ;
VAL_ 2332111005 M2I_Byrack_ReVeEnable_IMM16_13 0 "invalid" 1 "Read SW-Version" 2 "Read HW-Version" 3 "Barcode" ;
VAL_ 2332111006 M2I_Byrack_Enable_IMM16_14 1 "Deactive" 2 "Active" ;
VAL_ 2332111006 M2I_Byrack_ReVeEnable_IMM16_14 0 "invalid" 1 "Read SW-Version" 2 "Read HW-Version" 3 "Barcode" ;
VAL_ 2332111007 M2I_Byrack_Enable_IMM16_15 1 "Deactive" 2 "Active" ;
VAL_ 2332111007 M2I_Byrack_ReVeEnable_IMM16_15 0 "invalid" 1 "Read SW-Version" 2 "Read HW-Version" 3 "Barcode" ;
VAL_ 2332111008 M2I_Byrack_Enable_IMM16_16 1 "Deactive" 2 "Active" ;
VAL_ 2332111008 M2I_Byrack_ReVeEnable_IMM16_16 0 "invalid" 1 "Read SW-Version" 2 "Read HW-Version" 3 "Barcode" ;
VAL_ 2332111009 M2I_Byrack_Enable_IMM16_17 1 "Deactive" 2 "Active" ;
VAL_ 2332111009 M2I_Byrack_ReVeEnable_IMM16_17 0 "invalid" 1 "Read SW-Version" 2 "Read HW-Version" 3 "Barcode" ;
VAL_ 2332111010 M2I_Byrack_Enable_IMM16_18 1 "Deactive" 2 "Active" ;
VAL_ 2332111010 M2I_Byrack_ReVeEnable_IMM16_18 0 "invalid" 1 "Read SW-Version" 2 "Read HW-Version" 3 "Barcode" ;
VAL_ 2332111011 M2I_Byrack_Enable_IMM16_19 1 "Deactive" 2 "Active" ;
VAL_ 2332111011 M2I_Byrack_ReVeEnable_IMM16_19 0 "invalid" 1 "Read SW-Version" 2 "Read HW-Version" 3 "Barcode" ;
VAL_ 2332111012 M2I_Byrack_Enable_IMM16_20 1 "Deactive" 2 "Active" ;
VAL_ 2332111012 M2I_Byrack_ReVeEnable_IMM16_20 0 "invalid" 1 "Read SW-Version" 2 "Read HW-Version" 3 "Barcode" ;
VAL_ 2332111013 M2I_Byrack_Enable_IMM16_21 1 "Deactive" 2 "Active" ;
VAL_ 2332111013 M2I_Byrack_ReVeEnable_IMM16_21 0 "invalid" 1 "Read SW-Version" 2 "Read HW-Version" 3 "Barcode" ;
VAL_ 2332111014 M2I_Byrack_Enable_IMM16_22 1 "Deactive" 2 "Active" ;
VAL_ 2332111014 M2I_Byrack_ReVeEnable_IMM16_22 0 "invalid" 1 "Read SW-Version" 2 "Read HW-Version" 3 "Barcode" ;
VAL_ 2332111015 M2I_Byrack_Enable_IMM16_23 1 "Deactive" 2 "Active" ;
VAL_ 2332111015 M2I_Byrack_ReVeEnable_IMM16_23 0 "invalid" 1 "Read SW-Version" 2 "Read HW-Version" 3 "Barcode" ;
VAL_ 2332111016 M2I_Byrack_Enable_IMM16_24 1 "Deactive" 2 "Active" ;
VAL_ 2332111016 M2I_Byrack_ReVeEnable_IMM16_24 0 "invalid" 1 "Read SW-Version" 2 "Read HW-Version" 3 "Barcode" ;
VAL_ 2332111017 M2I_Byrack_Enable_IMM16_25 1 "Deactive" 2 "Active" ;
VAL_ 2332111017 M2I_Byrack_ReVeEnable_IMM16_25 0 "invalid" 1 "Read SW-Version" 2 "Read HW-Version" 3 "Barcode" ;
VAL_ 2332111018 M2I_Byrack_Enable_IMM16_26 1 "Deactive" 2 "Active" ;
VAL_ 2332111018 M2I_Byrack_ReVeEnable_IMM16_26 0 "invalid" 1 "Read SW-Version" 2 "Read HW-Version" 3 "Barcode" ;
VAL_ 2332111019 M2I_Byrack_Enable_IMM16_27 1 "Deactive" 2 "Active" ;
VAL_ 2332111019 M2I_Byrack_ReVeEnable_IMM16_27 0 "invalid" 1 "Read SW-Version" 2 "Read HW-Version" 3 "Barcode" ;
VAL_ 2332111020 M2I_Byrack_Enable_IMM16_28 1 "Deactive" 2 "Active" ;
VAL_ 2332111020 M2I_Byrack_ReVeEnable_IMM16_28 0 "invalid" 1 "Read SW-Version" 2 "Read HW-Version" 3 "Barcode" ;
VAL_ 2332111021 M2I_Byrack_Enable_IMM16_29 1 "Deactive" 2 "Active" ;
VAL_ 2332111021 M2I_Byrack_ReVeEnable_IMM16_29 0 "invalid" 1 "Read SW-Version" 2 "Read HW-Version" 3 "Barcode" ;
VAL_ 2332111022 M2I_Byrack_Enable_IMM16_30 1 "Deactive" 2 "Active" ;
VAL_ 2332111022 M2I_Byrack_ReVeEnable_IMM16_30 0 "invalid" 1 "Read SW-Version" 2 "Read HW-Version" 3 "Barcode" ;
VAL_ 2332111023 M2I_Byrack_Enable_IMM16_31 1 "Deactive" 2 "Active" ;
VAL_ 2332111023 M2I_Byrack_ReVeEnable_IMM16_31 0 "invalid" 1 "Read SW-Version" 2 "Read HW-Version" 3 "Barcode" ;
VAL_ 2332111249 M2I_Byrack_Enable_IMM17_01 1 "Deactive" 2 "Active" ;
VAL_ 2332111249 M2I_Byrack_ReVeEnable_IMM17_01 0 "invalid" 1 "Read SW-Version" 2 "Read HW-Version" 3 "Barcode" ;
VAL_ 2332111250 M2I_Byrack_Enable_IMM17_02 1 "Deactive" 2 "Active" ;
VAL_ 2332111250 M2I_Byrack_ReVeEnable_IMM17_02 0 "invalid" 1 "Read SW-Version" 2 "Read HW-Version" 3 "Barcode" ;
VAL_ 2332111251 M2I_Byrack_Enable_IMM17_03 1 "Deactive" 2 "Active" ;
VAL_ 2332111251 M2I_Byrack_ReVeEnable_IMM17_03 0 "invalid" 1 "Read SW-Version" 2 "Read HW-Version" 3 "Barcode" ;
VAL_ 2332111252 M2I_Byrack_Enable_IMM17_04 1 "Deactive" 2 "Active" ;
VAL_ 2332111252 M2I_Byrack_ReVeEnable_IMM17_04 0 "invalid" 1 "Read SW-Version" 2 "Read HW-Version" 3 "Barcode" ;
VAL_ 2332111253 M2I_Byrack_Enable_IMM17_05 1 "Deactive" 2 "Active" ;
VAL_ 2332111253 M2I_Byrack_ReVeEnable_IMM17_05 0 "invalid" 1 "Read SW-Version" 2 "Read HW-Version" 3 "Barcode" ;
VAL_ 2332111254 M2I_Byrack_Enable_IMM17_06 1 "Deactive" 2 "Active" ;
VAL_ 2332111254 M2I_Byrack_ReVeEnable_IMM17_06 0 "invalid" 1 "Read SW-Version" 2 "Read HW-Version" 3 "Barcode" ;
VAL_ 2332111255 M2I_Byrack_Enable_IMM17_07 1 "Deactive" 2 "Active" ;
VAL_ 2332111255 M2I_Byrack_ReVeEnable_IMM17_07 0 "invalid" 1 "Read SW-Version" 2 "Read HW-Version" 3 "Barcode" ;
VAL_ 2332111256 M2I_Byrack_Enable_IMM17_08 1 "Deactive" 2 "Active" ;
VAL_ 2332111256 M2I_Byrack_ReVeEnable_IMM17_08 0 "invalid" 1 "Read SW-Version" 2 "Read HW-Version" 3 "Barcode" ;
VAL_ 2332111257 M2I_Byrack_Enable_IMM17_09 1 "Deactive" 2 "Active" ;
VAL_ 2332111257 M2I_Byrack_ReVeEnable_IMM17_09 0 "invalid" 1 "Read SW-Version" 2 "Read HW-Version" 3 "Barcode" ;
VAL_ 2332111258 M2I_Byrack_Enable_IMM17_10 1 "Deactive" 2 "Active" ;
VAL_ 2332111258 M2I_Byrack_ReVeEnable_IMM17_10 0 "invalid" 1 "Read SW-Version" 2 "Read HW-Version" 3 "Barcode" ;
VAL_ 2332111259 M2I_Byrack_Enable_IMM17_11 1 "Deactive" 2 "Active" ;
VAL_ 2332111259 M2I_Byrack_ReVeEnable_IMM17_11 0 "invalid" 1 "Read SW-Version" 2 "Read HW-Version" 3 "Barcode" ;
VAL_ 2332111260 M2I_Byrack_Enable_IMM17_12 1 "Deactive" 2 "Active" ;
VAL_ 2332111260 M2I_Byrack_ReVeEnable_IMM17_12 0 "invalid" 1 "Read SW-Version" 2 "Read HW-Version" 3 "Barcode" ;
VAL_ 2332111261 M2I_Byrack_Enable_IMM17_13 1 "Deactive" 2 "Active" ;
VAL_ 2332111261 M2I_Byrack_ReVeEnable_IMM17_13 0 "invalid" 1 "Read SW-Version" 2 "Read HW-Version" 3 "Barcode" ;
VAL_ 2332111262 M2I_Byrack_Enable_IMM17_14 1 "Deactive" 2 "Active" ;
VAL_ 2332111262 M2I_Byrack_ReVeEnable_IMM17_14 0 "invalid" 1 "Read SW-Version" 2 "Read HW-Version" 3 "Barcode" ;
VAL_ 2332111263 M2I_Byrack_Enable_IMM17_15 1 "Deactive" 2 "Active" ;
VAL_ 2332111263 M2I_Byrack_ReVeEnable_IMM17_15 0 "invalid" 1 "Read SW-Version" 2 "Read HW-Version" 3 "Barcode" ;
VAL_ 2332111264 M2I_Byrack_Enable_IMM17_16 1 "Deactive" 2 "Active" ;
VAL_ 2332111264 M2I_Byrack_ReVeEnable_IMM17_16 0 "invalid" 1 "Read SW-Version" 2 "Read HW-Version" 3 "Barcode" ;
VAL_ 2332111265 M2I_Byrack_Enable_IMM17_17 1 "Deactive" 2 "Active" ;
VAL_ 2332111265 M2I_Byrack_ReVeEnable_IMM17_17 0 "invalid" 1 "Read SW-Version" 2 "Read HW-Version" 3 "Barcode" ;
VAL_ 2332111266 M2I_Byrack_Enable_IMM17_18 1 "Deactive" 2 "Active" ;
VAL_ 2332111266 M2I_Byrack_ReVeEnable_IMM17_18 0 "invalid" 1 "Read SW-Version" 2 "Read HW-Version" 3 "Barcode" ;
VAL_ 2332111267 M2I_Byrack_Enable_IMM17_19 1 "Deactive" 2 "Active" ;
VAL_ 2332111267 M2I_Byrack_ReVeEnable_IMM17_19 0 "invalid" 1 "Read SW-Version" 2 "Read HW-Version" 3 "Barcode" ;
VAL_ 2332111268 M2I_Byrack_Enable_IMM17_20 1 "Deactive" 2 "Active" ;
VAL_ 2332111268 M2I_Byrack_ReVeEnable_IMM17_20 0 "invalid" 1 "Read SW-Version" 2 "Read HW-Version" 3 "Barcode" ;
VAL_ 2332111269 M2I_Byrack_Enable_IMM17_21 1 "Deactive" 2 "Active" ;
VAL_ 2332111269 M2I_Byrack_ReVeEnable_IMM17_21 0 "invalid" 1 "Read SW-Version" 2 "Read HW-Version" 3 "Barcode" ;
VAL_ 2332111270 M2I_Byrack_Enable_IMM17_22 1 "Deactive" 2 "Active" ;
VAL_ 2332111270 M2I_Byrack_ReVeEnable_IMM17_22 0 "invalid" 1 "Read SW-Version" 2 "Read HW-Version" 3 "Barcode" ;
VAL_ 2332111271 M2I_Byrack_Enable_IMM17_23 1 "Deactive" 2 "Active" ;
VAL_ 2332111271 M2I_Byrack_ReVeEnable_IMM17_23 0 "invalid" 1 "Read SW-Version" 2 "Read HW-Version" 3 "Barcode" ;
VAL_ 2332111272 M2I_Byrack_Enable_IMM17_24 1 "Deactive" 2 "Active" ;
VAL_ 2332111272 M2I_Byrack_ReVeEnable_IMM17_24 0 "invalid" 1 "Read SW-Version" 2 "Read HW-Version" 3 "Barcode" ;
VAL_ 2332111273 M2I_Byrack_Enable_IMM17_25 1 "Deactive" 2 "Active" ;
VAL_ 2332111273 M2I_Byrack_ReVeEnable_IMM17_25 0 "invalid" 1 "Read SW-Version" 2 "Read HW-Version" 3 "Barcode" ;
VAL_ 2332111274 M2I_Byrack_Enable_IMM17_26 1 "Deactive" 2 "Active" ;
VAL_ 2332111274 M2I_Byrack_ReVeEnable_IMM17_26 0 "invalid" 1 "Read SW-Version" 2 "Read HW-Version" 3 "Barcode" ;
VAL_ 2332111275 M2I_Byrack_Enable_IMM17_27 1 "Deactive" 2 "Active" ;
VAL_ 2332111275 M2I_Byrack_ReVeEnable_IMM17_27 0 "invalid" 1 "Read SW-Version" 2 "Read HW-Version" 3 "Barcode" ;
VAL_ 2332111276 M2I_Byrack_Enable_IMM17_28 1 "Deactive" 2 "Active" ;
VAL_ 2332111276 M2I_Byrack_ReVeEnable_IMM17_28 0 "invalid" 1 "Read SW-Version" 2 "Read HW-Version" 3 "Barcode" ;
VAL_ 2332111277 M2I_Byrack_Enable_IMM17_29 1 "Deactive" 2 "Active" ;
VAL_ 2332111277 M2I_Byrack_ReVeEnable_IMM17_29 0 "invalid" 1 "Read SW-Version" 2 "Read HW-Version" 3 "Barcode" ;
VAL_ 2332111278 M2I_Byrack_Enable_IMM17_30 1 "Deactive" 2 "Active" ;
VAL_ 2332111278 M2I_Byrack_ReVeEnable_IMM17_30 0 "invalid" 1 "Read SW-Version" 2 "Read HW-Version" 3 "Barcode" ;
VAL_ 2332111279 M2I_Byrack_Enable_IMM17_31 1 "Deactive" 2 "Active" ;
VAL_ 2332111279 M2I_Byrack_ReVeEnable_IMM17_31 0 "invalid" 1 "Read SW-Version" 2 "Read HW-Version" 3 "Barcode" ;
VAL_ 2332111505 M2I_Byrack_Enable_IMM18_01 1 "Deactive" 2 "Active" ;
VAL_ 2332111505 M2I_Byrack_ReVeEnable_IMM18_01 0 "invalid" 1 "Read SW-Version" 2 "Read HW-Version" 3 "Barcode" ;
VAL_ 2332111506 M2I_Byrack_Enable_IMM18_02 1 "Deactive" 2 "Active" ;
VAL_ 2332111506 M2I_Byrack_ReVeEnable_IMM18_02 0 "invalid" 1 "Read SW-Version" 2 "Read HW-Version" 3 "Barcode" ;
VAL_ 2332111507 M2I_Byrack_Enable_IMM18_03 1 "Deactive" 2 "Active" ;
VAL_ 2332111507 M2I_Byrack_ReVeEnable_IMM18_03 0 "invalid" 1 "Read SW-Version" 2 "Read HW-Version" 3 "Barcode" ;
VAL_ 2332111508 M2I_Byrack_Enable_IMM18_04 1 "Deactive" 2 "Active" ;
VAL_ 2332111508 M2I_Byrack_ReVeEnable_IMM18_04 0 "invalid" 1 "Read SW-Version" 2 "Read HW-Version" 3 "Barcode" ;
VAL_ 2332111509 M2I_Byrack_Enable_IMM18_05 1 "Deactive" 2 "Active" ;
VAL_ 2332111509 M2I_Byrack_ReVeEnable_IMM18_05 0 "invalid" 1 "Read SW-Version" 2 "Read HW-Version" 3 "Barcode" ;
VAL_ 2332111510 M2I_Byrack_Enable_IMM18_06 1 "Deactive" 2 "Active" ;
VAL_ 2332111510 M2I_Byrack_ReVeEnable_IMM18_06 0 "invalid" 1 "Read SW-Version" 2 "Read HW-Version" 3 "Barcode" ;
VAL_ 2332111511 M2I_Byrack_Enable_IMM18_07 1 "Deactive" 2 "Active" ;
VAL_ 2332111511 M2I_Byrack_ReVeEnable_IMM18_07 0 "invalid" 1 "Read SW-Version" 2 "Read HW-Version" 3 "Barcode" ;
VAL_ 2332111512 M2I_Byrack_Enable_IMM18_08 1 "Deactive" 2 "Active" ;
VAL_ 2332111512 M2I_Byrack_ReVeEnable_IMM18_08 0 "invalid" 1 "Read SW-Version" 2 "Read HW-Version" 3 "Barcode" ;
VAL_ 2332111513 M2I_Byrack_Enable_IMM18_09 1 "Deactive" 2 "Active" ;
VAL_ 2332111513 M2I_Byrack_ReVeEnable_IMM18_09 0 "invalid" 1 "Read SW-Version" 2 "Read HW-Version" 3 "Barcode" ;
VAL_ 2332111514 M2I_Byrack_Enable_IMM18_10 1 "Deactive" 2 "Active" ;
VAL_ 2332111514 M2I_Byrack_ReVeEnable_IMM18_10 0 "invalid" 1 "Read SW-Version" 2 "Read HW-Version" 3 "Barcode" ;
VAL_ 2332111515 M2I_Byrack_Enable_IMM18_11 1 "Deactive" 2 "Active" ;
VAL_ 2332111515 M2I_Byrack_ReVeEnable_IMM18_11 0 "invalid" 1 "Read SW-Version" 2 "Read HW-Version" 3 "Barcode" ;
VAL_ 2332111516 M2I_Byrack_Enable_IMM18_12 1 "Deactive" 2 "Active" ;
VAL_ 2332111516 M2I_Byrack_ReVeEnable_IMM18_12 0 "invalid" 1 "Read SW-Version" 2 "Read HW-Version" 3 "Barcode" ;
VAL_ 2332111517 M2I_Byrack_Enable_IMM18_13 1 "Deactive" 2 "Active" ;
VAL_ 2332111517 M2I_Byrack_ReVeEnable_IMM18_13 0 "invalid" 1 "Read SW-Version" 2 "Read HW-Version" 3 "Barcode" ;
VAL_ 2332111518 M2I_Byrack_Enable_IMM18_14 1 "Deactive" 2 "Active" ;
VAL_ 2332111518 M2I_Byrack_ReVeEnable_IMM18_14 0 "invalid" 1 "Read SW-Version" 2 "Read HW-Version" 3 "Barcode" ;
VAL_ 2332111519 M2I_Byrack_Enable_IMM18_15 1 "Deactive" 2 "Active" ;
VAL_ 2332111519 M2I_Byrack_ReVeEnable_IMM18_15 0 "invalid" 1 "Read SW-Version" 2 "Read HW-Version" 3 "Barcode" ;
VAL_ 2332111520 M2I_Byrack_Enable_IMM18_16 1 "Deactive" 2 "Active" ;
VAL_ 2332111520 M2I_Byrack_ReVeEnable_IMM18_16 0 "invalid" 1 "Read SW-Version" 2 "Read HW-Version" 3 "Barcode" ;
VAL_ 2332111521 M2I_Byrack_Enable_IMM18_17 1 "Deactive" 2 "Active" ;
VAL_ 2332111521 M2I_Byrack_ReVeEnable_IMM18_17 0 "invalid" 1 "Read SW-Version" 2 "Read HW-Version" 3 "Barcode" ;
VAL_ 2332111522 M2I_Byrack_Enable_IMM18_18 1 "Deactive" 2 "Active" ;
VAL_ 2332111522 M2I_Byrack_ReVeEnable_IMM18_18 0 "invalid" 1 "Read SW-Version" 2 "Read HW-Version" 3 "Barcode" ;
VAL_ 2332111523 M2I_Byrack_Enable_IMM18_19 1 "Deactive" 2 "Active" ;
VAL_ 2332111523 M2I_Byrack_ReVeEnable_IMM18_19 0 "invalid" 1 "Read SW-Version" 2 "Read HW-Version" 3 "Barcode" ;
VAL_ 2332111524 M2I_Byrack_Enable_IMM18_20 1 "Deactive" 2 "Active" ;
VAL_ 2332111524 M2I_Byrack_ReVeEnable_IMM18_20 0 "invalid" 1 "Read SW-Version" 2 "Read HW-Version" 3 "Barcode" ;
VAL_ 2332111525 M2I_Byrack_Enable_IMM18_21 1 "Deactive" 2 "Active" ;
VAL_ 2332111525 M2I_Byrack_ReVeEnable_IMM18_21 0 "invalid" 1 "Read SW-Version" 2 "Read HW-Version" 3 "Barcode" ;
VAL_ 2332111526 M2I_Byrack_Enable_IMM18_22 1 "Deactive" 2 "Active" ;
VAL_ 2332111526 M2I_Byrack_ReVeEnable_IMM18_22 0 "invalid" 1 "Read SW-Version" 2 "Read HW-Version" 3 "Barcode" ;
VAL_ 2332111527 M2I_Byrack_Enable_IMM18_23 1 "Deactive" 2 "Active" ;
VAL_ 2332111527 M2I_Byrack_ReVeEnable_IMM18_23 0 "invalid" 1 "Read SW-Version" 2 "Read HW-Version" 3 "Barcode" ;
VAL_ 2332111528 M2I_Byrack_Enable_IMM18_24 1 "Deactive" 2 "Active" ;
VAL_ 2332111528 M2I_Byrack_ReVeEnable_IMM18_24 0 "invalid" 1 "Read SW-Version" 2 "Read HW-Version" 3 "Barcode" ;
VAL_ 2332111529 M2I_Byrack_Enable_IMM18_25 1 "Deactive" 2 "Active" ;
VAL_ 2332111529 M2I_Byrack_ReVeEnable_IMM18_25 0 "invalid" 1 "Read SW-Version" 2 "Read HW-Version" 3 "Barcode" ;
VAL_ 2332111530 M2I_Byrack_Enable_IMM18_26 1 "Deactive" 2 "Active" ;
VAL_ 2332111530 M2I_Byrack_ReVeEnable_IMM18_26 0 "invalid" 1 "Read SW-Version" 2 "Read HW-Version" 3 "Barcode" ;
VAL_ 2332111531 M2I_Byrack_Enable_IMM18_27 1 "Deactive" 2 "Active" ;
VAL_ 2332111531 M2I_Byrack_ReVeEnable_IMM18_27 0 "invalid" 1 "Read SW-Version" 2 "Read HW-Version" 3 "Barcode" ;
VAL_ 2332111532 M2I_Byrack_Enable_IMM18_28 1 "Deactive" 2 "Active" ;
VAL_ 2332111532 M2I_Byrack_ReVeEnable_IMM18_28 0 "invalid" 1 "Read SW-Version" 2 "Read HW-Version" 3 "Barcode" ;
VAL_ 2332111533 M2I_Byrack_Enable_IMM18_29 1 "Deactive" 2 "Active" ;
VAL_ 2332111533 M2I_Byrack_ReVeEnable_IMM18_29 0 "invalid" 1 "Read SW-Version" 2 "Read HW-Version" 3 "Barcode" ;
VAL_ 2332111534 M2I_Byrack_Enable_IMM18_30 1 "Deactive" 2 "Active" ;
VAL_ 2332111534 M2I_Byrack_ReVeEnable_IMM18_30 0 "invalid" 1 "Read SW-Version" 2 "Read HW-Version" 3 "Barcode" ;
VAL_ 2332111535 M2I_Byrack_Enable_IMM18_31 1 "Deactive" 2 "Active" ;
VAL_ 2332111535 M2I_Byrack_ReVeEnable_IMM18_31 0 "invalid" 1 "Read SW-Version" 2 "Read HW-Version" 3 "Barcode" ;
VAL_ 2332111761 M2I_Byrack_Enable_IMM9_01 1 "Deactive" 2 "Active" ;
VAL_ 2332111761 M2I_Byrack_ReVeEnable_IMM19_01 0 "invalid" 1 "Read SW-Version" 2 "Read HW-Version" 3 "Barcode" ;
VAL_ 2332111762 M2I_Byrack_Enable_IMM9_02 1 "Deactive" 2 "Active" ;
VAL_ 2332111762 M2I_Byrack_ReVeEnable_IMM19_02 0 "invalid" 1 "Read SW-Version" 2 "Read HW-Version" 3 "Barcode" ;
VAL_ 2332111763 M2I_Byrack_Enable_IMM9_03 1 "Deactive" 2 "Active" ;
VAL_ 2332111763 M2I_Byrack_ReVeEnable_IMM19_03 0 "invalid" 1 "Read SW-Version" 2 "Read HW-Version" 3 "Barcode" ;
VAL_ 2332111764 M2I_Byrack_Enable_IMM9_04 1 "Deactive" 2 "Active" ;
VAL_ 2332111764 M2I_Byrack_ReVeEnable_IMM19_04 0 "invalid" 1 "Read SW-Version" 2 "Read HW-Version" 3 "Barcode" ;
VAL_ 2332111765 M2I_Byrack_Enable_IMM9_05 1 "Deactive" 2 "Active" ;
VAL_ 2332111765 M2I_Byrack_ReVeEnable_IMM19_05 0 "invalid" 1 "Read SW-Version" 2 "Read HW-Version" 3 "Barcode" ;
VAL_ 2332111766 M2I_Byrack_Enable_IMM9_06 1 "Deactive" 2 "Active" ;
VAL_ 2332111766 M2I_Byrack_ReVeEnable_IMM19_06 0 "invalid" 1 "Read SW-Version" 2 "Read HW-Version" 3 "Barcode" ;
VAL_ 2332111767 M2I_Byrack_Enable_IMM9_07 1 "Deactive" 2 "Active" ;
VAL_ 2332111767 M2I_Byrack_ReVeEnable_IMM19_07 0 "invalid" 1 "Read SW-Version" 2 "Read HW-Version" 3 "Barcode" ;
VAL_ 2332111768 M2I_Byrack_Enable_IMM9_08 1 "Deactive" 2 "Active" ;
VAL_ 2332111768 M2I_Byrack_ReVeEnable_IMM19_08 0 "invalid" 1 "Read SW-Version" 2 "Read HW-Version" 3 "Barcode" ;
VAL_ 2332111769 M2I_Byrack_Enable_IMM9_09 1 "Deactive" 2 "Active" ;
VAL_ 2332111769 M2I_Byrack_ReVeEnable_IMM19_09 0 "invalid" 1 "Read SW-Version" 2 "Read HW-Version" 3 "Barcode" ;
VAL_ 2332111770 M2I_Byrack_Enable_IMM9_10 1 "Deactive" 2 "Active" ;
VAL_ 2332111770 M2I_Byrack_ReVeEnable_IMM19_10 0 "invalid" 1 "Read SW-Version" 2 "Read HW-Version" 3 "Barcode" ;
VAL_ 2332111771 M2I_Byrack_Enable_IMM9_11 1 "Deactive" 2 "Active" ;
VAL_ 2332111771 M2I_Byrack_ReVeEnable_IMM19_11 0 "invalid" 1 "Read SW-Version" 2 "Read HW-Version" 3 "Barcode" ;
VAL_ 2332111772 M2I_Byrack_Enable_IMM9_12 1 "Deactive" 2 "Active" ;
VAL_ 2332111772 M2I_Byrack_ReVeEnable_IMM19_12 0 "invalid" 1 "Read SW-Version" 2 "Read HW-Version" 3 "Barcode" ;
VAL_ 2332111773 M2I_Byrack_Enable_IMM9_13 1 "Deactive" 2 "Active" ;
VAL_ 2332111773 M2I_Byrack_ReVeEnable_IMM19_13 0 "invalid" 1 "Read SW-Version" 2 "Read HW-Version" 3 "Barcode" ;
VAL_ 2332111774 M2I_Byrack_Enable_IMM9_14 1 "Deactive" 2 "Active" ;
VAL_ 2332111774 M2I_Byrack_ReVeEnable_IMM19_14 0 "invalid" 1 "Read SW-Version" 2 "Read HW-Version" 3 "Barcode" ;
VAL_ 2332111775 M2I_Byrack_Enable_IMM9_15 1 "Deactive" 2 "Active" ;
VAL_ 2332111775 M2I_Byrack_ReVeEnable_IMM19_15 0 "invalid" 1 "Read SW-Version" 2 "Read HW-Version" 3 "Barcode" ;
VAL_ 2332111776 M2I_Byrack_Enable_IMM9_16 1 "Deactive" 2 "Active" ;
VAL_ 2332111776 M2I_Byrack_ReVeEnable_IMM19_16 0 "invalid" 1 "Read SW-Version" 2 "Read HW-Version" 3 "Barcode" ;
VAL_ 2332111777 M2I_Byrack_Enable_IMM9_17 1 "Deactive" 2 "Active" ;
VAL_ 2332111777 M2I_Byrack_ReVeEnable_IMM19_17 0 "invalid" 1 "Read SW-Version" 2 "Read HW-Version" 3 "Barcode" ;
VAL_ 2332111778 M2I_Byrack_Enable_IMM9_18 1 "Deactive" 2 "Active" ;
VAL_ 2332111778 M2I_Byrack_ReVeEnable_IMM19_18 0 "invalid" 1 "Read SW-Version" 2 "Read HW-Version" 3 "Barcode" ;
VAL_ 2332111779 M2I_Byrack_Enable_IMM9_19 1 "Deactive" 2 "Active" ;
VAL_ 2332111779 M2I_Byrack_ReVeEnable_IMM19_19 0 "invalid" 1 "Read SW-Version" 2 "Read HW-Version" 3 "Barcode" ;
VAL_ 2332111780 M2I_Byrack_Enable_IMM9_20 1 "Deactive" 2 "Active" ;
VAL_ 2332111780 M2I_Byrack_ReVeEnable_IMM19_20 0 "invalid" 1 "Read SW-Version" 2 "Read HW-Version" 3 "Barcode" ;
VAL_ 2332111781 M2I_Byrack_Enable_IMM9_21 1 "Deactive" 2 "Active" ;
VAL_ 2332111781 M2I_Byrack_ReVeEnable_IMM19_21 0 "invalid" 1 "Read SW-Version" 2 "Read HW-Version" 3 "Barcode" ;
VAL_ 2332111782 M2I_Byrack_Enable_IMM9_22 1 "Deactive" 2 "Active" ;
VAL_ 2332111782 M2I_Byrack_ReVeEnable_IMM19_22 0 "invalid" 1 "Read SW-Version" 2 "Read HW-Version" 3 "Barcode" ;
VAL_ 2332111783 M2I_Byrack_Enable_IMM9_23 1 "Deactive" 2 "Active" ;
VAL_ 2332111783 M2I_Byrack_ReVeEnable_IMM19_23 0 "invalid" 1 "Read SW-Version" 2 "Read HW-Version" 3 "Barcode" ;
VAL_ 2332111784 M2I_Byrack_Enable_IMM9_24 1 "Deactive" 2 "Active" ;
VAL_ 2332111784 M2I_Byrack_ReVeEnable_IMM19_24 0 "invalid" 1 "Read SW-Version" 2 "Read HW-Version" 3 "Barcode" ;
VAL_ 2332111785 M2I_Byrack_Enable_IMM9_25 1 "Deactive" 2 "Active" ;
VAL_ 2332111785 M2I_Byrack_ReVeEnable_IMM19_25 0 "invalid" 1 "Read SW-Version" 2 "Read HW-Version" 3 "Barcode" ;
VAL_ 2332111786 M2I_Byrack_Enable_IMM9_26 1 "Deactive" 2 "Active" ;
VAL_ 2332111786 M2I_Byrack_ReVeEnable_IMM19_26 0 "invalid" 1 "Read SW-Version" 2 "Read HW-Version" 3 "Barcode" ;
VAL_ 2332111787 M2I_Byrack_Enable_IMM9_27 1 "Deactive" 2 "Active" ;
VAL_ 2332111787 M2I_Byrack_ReVeEnable_IMM19_27 0 "invalid" 1 "Read SW-Version" 2 "Read HW-Version" 3 "Barcode" ;
VAL_ 2332111788 M2I_Byrack_Enable_IMM9_28 1 "Deactive" 2 "Active" ;
VAL_ 2332111788 M2I_Byrack_ReVeEnable_IMM19_28 0 "invalid" 1 "Read SW-Version" 2 "Read HW-Version" 3 "Barcode" ;
VAL_ 2332111789 M2I_Byrack_Enable_IMM9_29 1 "Deactive" 2 "Active" ;
VAL_ 2332111789 M2I_Byrack_ReVeEnable_IMM19_29 0 "invalid" 1 "Read SW-Version" 2 "Read HW-Version" 3 "Barcode" ;
VAL_ 2332111790 M2I_Byrack_Enable_IMM9_30 1 "Deactive" 2 "Active" ;
VAL_ 2332111790 M2I_Byrack_ReVeEnable_IMM19_30 0 "invalid" 1 "Read SW-Version" 2 "Read HW-Version" 3 "Barcode" ;
VAL_ 2332111791 M2I_Byrack_Enable_IMM9_31 1 "Deactive" 2 "Active" ;
VAL_ 2332111791 M2I_Byrack_ReVeEnable_IMM19_31 0 "invalid" 1 "Read SW-Version" 2 "Read HW-Version" 3 "Barcode" ;
VAL_ 2332112017 M2I_Byrack_Enable_IMM20_01 1 "Deactive" 2 "Active" ;
VAL_ 2332112017 M2I_Byrack_ReVeEnable_IMM20_01 0 "invalid" 1 "Read SW-Version" 2 "Read HW-Version" 3 "Barcode" ;
VAL_ 2332112018 M2I_Byrack_Enable_IMM20_02 1 "Deactive" 2 "Active" ;
VAL_ 2332112018 M2I_Byrack_ReVeEnable_IMM20_02 0 "invalid" 1 "Read SW-Version" 2 "Read HW-Version" 3 "Barcode" ;
VAL_ 2332112019 M2I_Byrack_Enable_IMM20_03 1 "Deactive" 2 "Active" ;
VAL_ 2332112019 M2I_Byrack_ReVeEnable_IMM20_03 0 "invalid" 1 "Read SW-Version" 2 "Read HW-Version" 3 "Barcode" ;
VAL_ 2332112020 M2I_Byrack_Enable_IMM20_04 1 "Deactive" 2 "Active" ;
VAL_ 2332112020 M2I_Byrack_ReVeEnable_IMM20_04 0 "invalid" 1 "Read SW-Version" 2 "Read HW-Version" 3 "Barcode" ;
VAL_ 2332112021 M2I_Byrack_Enable_IMM20_05 1 "Deactive" 2 "Active" ;
VAL_ 2332112021 M2I_Byrack_ReVeEnable_IMM20_05 0 "invalid" 1 "Read SW-Version" 2 "Read HW-Version" 3 "Barcode" ;
VAL_ 2332112022 M2I_Byrack_Enable_IMM20_06 1 "Deactive" 2 "Active" ;
VAL_ 2332112022 M2I_Byrack_ReVeEnable_IMM20_06 0 "invalid" 1 "Read SW-Version" 2 "Read HW-Version" 3 "Barcode" ;
VAL_ 2332112023 M2I_Byrack_Enable_IMM20_07 1 "Deactive" 2 "Active" ;
VAL_ 2332112023 M2I_Byrack_ReVeEnable_IMM20_07 0 "invalid" 1 "Read SW-Version" 2 "Read HW-Version" 3 "Barcode" ;
VAL_ 2332112024 M2I_Byrack_Enable_IMM20_08 1 "Deactive" 2 "Active" ;
VAL_ 2332112024 M2I_Byrack_ReVeEnable_IMM20_08 0 "invalid" 1 "Read SW-Version" 2 "Read HW-Version" 3 "Barcode" ;
VAL_ 2332112025 M2I_Byrack_Enable_IMM20_09 1 "Deactive" 2 "Active" ;
VAL_ 2332112025 M2I_Byrack_ReVeEnable_IMM20_09 0 "invalid" 1 "Read SW-Version" 2 "Read HW-Version" 3 "Barcode" ;
VAL_ 2332112026 M2I_Byrack_Enable_IMM20_10 1 "Deactive" 2 "Active" ;
VAL_ 2332112026 M2I_Byrack_ReVeEnable_IMM20_10 0 "invalid" 1 "Read SW-Version" 2 "Read HW-Version" 3 "Barcode" ;
VAL_ 2332112027 M2I_Byrack_Enable_IMM20_11 1 "Deactive" 2 "Active" ;
VAL_ 2332112027 M2I_Byrack_ReVeEnable_IMM20_11 0 "invalid" 1 "Read SW-Version" 2 "Read HW-Version" 3 "Barcode" ;
VAL_ 2332112028 M2I_Byrack_Enable_IMM20_12 1 "Deactive" 2 "Active" ;
VAL_ 2332112028 M2I_Byrack_ReVeEnable_IMM20_12 0 "invalid" 1 "Read SW-Version" 2 "Read HW-Version" 3 "Barcode" ;
VAL_ 2332112029 M2I_Byrack_Enable_IMM20_13 1 "Deactive" 2 "Active" ;
VAL_ 2332112029 M2I_Byrack_ReVeEnable_IMM20_13 0 "invalid" 1 "Read SW-Version" 2 "Read HW-Version" 3 "Barcode" ;
VAL_ 2332112030 M2I_Byrack_Enable_IMM20_14 1 "Deactive" 2 "Active" ;
VAL_ 2332112030 M2I_Byrack_ReVeEnable_IMM20_14 0 "invalid" 1 "Read SW-Version" 2 "Read HW-Version" 3 "Barcode" ;
VAL_ 2332112031 M2I_Byrack_Enable_IMM20_15 1 "Deactive" 2 "Active" ;
VAL_ 2332112031 M2I_Byrack_ReVeEnable_IMM20_15 0 "invalid" 1 "Read SW-Version" 2 "Read HW-Version" 3 "Barcode" ;
VAL_ 2332112032 M2I_Byrack_Enable_IMM20_16 1 "Deactive" 2 "Active" ;
VAL_ 2332112032 M2I_Byrack_ReVeEnable_IMM20_16 0 "invalid" 1 "Read SW-Version" 2 "Read HW-Version" 3 "Barcode" ;
VAL_ 2332112033 M2I_Byrack_Enable_IMM20_17 1 "Deactive" 2 "Active" ;
VAL_ 2332112033 M2I_Byrack_ReVeEnable_IMM20_17 0 "invalid" 1 "Read SW-Version" 2 "Read HW-Version" 3 "Barcode" ;
VAL_ 2332112034 M2I_Byrack_Enable_IMM20_18 1 "Deactive" 2 "Active" ;
VAL_ 2332112034 M2I_Byrack_ReVeEnable_IMM20_18 0 "invalid" 1 "Read SW-Version" 2 "Read HW-Version" 3 "Barcode" ;
VAL_ 2332112035 M2I_Byrack_Enable_IMM20_19 1 "Deactive" 2 "Active" ;
VAL_ 2332112035 M2I_Byrack_ReVeEnable_IMM20_19 0 "invalid" 1 "Read SW-Version" 2 "Read HW-Version" 3 "Barcode" ;
VAL_ 2332112036 M2I_Byrack_Enable_IMM20_20 1 "Deactive" 2 "Active" ;
VAL_ 2332112036 M2I_Byrack_ReVeEnable_IMM20_20 0 "invalid" 1 "Read SW-Version" 2 "Read HW-Version" 3 "Barcode" ;
VAL_ 2332112037 M2I_Byrack_Enable_IMM20_21 1 "Deactive" 2 "Active" ;
VAL_ 2332112037 M2I_Byrack_ReVeEnable_IMM20_21 0 "invalid" 1 "Read SW-Version" 2 "Read HW-Version" 3 "Barcode" ;
VAL_ 2332112038 M2I_Byrack_Enable_IMM20_22 1 "Deactive" 2 "Active" ;
VAL_ 2332112038 M2I_Byrack_ReVeEnable_IMM20_22 0 "invalid" 1 "Read SW-Version" 2 "Read HW-Version" 3 "Barcode" ;
VAL_ 2332112039 M2I_Byrack_Enable_IMM20_23 1 "Deactive" 2 "Active" ;
VAL_ 2332112039 M2I_Byrack_ReVeEnable_IMM20_23 0 "invalid" 1 "Read SW-Version" 2 "Read HW-Version" 3 "Barcode" ;
VAL_ 2332112040 M2I_Byrack_Enable_IMM20_24 1 "Deactive" 2 "Active" ;
VAL_ 2332112040 M2I_Byrack_ReVeEnable_IMM20_24 0 "invalid" 1 "Read SW-Version" 2 "Read HW-Version" 3 "Barcode" ;
VAL_ 2332112041 M2I_Byrack_Enable_IMM20_25 1 "Deactive" 2 "Active" ;
VAL_ 2332112041 M2I_Byrack_ReVeEnable_IMM20_25 0 "invalid" 1 "Read SW-Version" 2 "Read HW-Version" 3 "Barcode" ;
VAL_ 2332112042 M2I_Byrack_Enable_IMM20_26 1 "Deactive" 2 "Active" ;
VAL_ 2332112042 M2I_Byrack_ReVeEnable_IMM20_26 0 "invalid" 1 "Read SW-Version" 2 "Read HW-Version" 3 "Barcode" ;
VAL_ 2332112043 M2I_Byrack_Enable_IMM20_27 1 "Deactive" 2 "Active" ;
VAL_ 2332112043 M2I_Byrack_ReVeEnable_IMM20_27 0 "invalid" 1 "Read SW-Version" 2 "Read HW-Version" 3 "Barcode" ;
VAL_ 2332112044 M2I_Byrack_Enable_IMM20_28 1 "Deactive" 2 "Active" ;
VAL_ 2332112044 M2I_Byrack_ReVeEnable_IMM20_28 0 "invalid" 1 "Read SW-Version" 2 "Read HW-Version" 3 "Barcode" ;
VAL_ 2332112045 M2I_Byrack_Enable_IMM20_29 1 "Deactive" 2 "Active" ;
VAL_ 2332112045 M2I_Byrack_ReVeEnable_IMM20_29 0 "invalid" 1 "Read SW-Version" 2 "Read HW-Version" 3 "Barcode" ;
VAL_ 2332112046 M2I_Byrack_Enable_IMM20_30 1 "Deactive" 2 "Active" ;
VAL_ 2332112046 M2I_Byrack_ReVeEnable_IMM20_30 0 "invalid" 1 "Read SW-Version" 2 "Read HW-Version" 3 "Barcode" ;
VAL_ 2332112047 M2I_Byrack_Enable_IMM20_31 1 "Deactive" 2 "Active" ;
VAL_ 2332112047 M2I_Byrack_ReVeEnable_IMM20_31 0 "invalid" 1 "Read SW-Version" 2 "Read HW-Version" 3 "Barcode" ;
VAL_ 2332112273 M2I_Byrack_Enable_IMM21_01 1 "Deactive" 2 "Active" ;
VAL_ 2332112273 M2I_Byrack_ReVeEnable_IMM21_01 0 "invalid" 1 "Read SW-Version" 2 "Read HW-Version" 3 "Barcode" ;
VAL_ 2332112274 M2I_Byrack_Enable_IMM21_02 1 "Deactive" 2 "Active" ;
VAL_ 2332112274 M2I_Byrack_ReVeEnable_IMM21_02 0 "invalid" 1 "Read SW-Version" 2 "Read HW-Version" 3 "Barcode" ;
VAL_ 2332112275 M2I_Byrack_Enable_IMM21_03 1 "Deactive" 2 "Active" ;
VAL_ 2332112275 M2I_Byrack_ReVeEnable_IMM21_03 0 "invalid" 1 "Read SW-Version" 2 "Read HW-Version" 3 "Barcode" ;
VAL_ 2332112276 M2I_Byrack_Enable_IMM21_04 1 "Deactive" 2 "Active" ;
VAL_ 2332112276 M2I_Byrack_ReVeEnable_IMM21_04 0 "invalid" 1 "Read SW-Version" 2 "Read HW-Version" 3 "Barcode" ;
VAL_ 2332112277 M2I_Byrack_Enable_IMM21_05 1 "Deactive" 2 "Active" ;
VAL_ 2332112277 M2I_Byrack_ReVeEnable_IMM21_05 0 "invalid" 1 "Read SW-Version" 2 "Read HW-Version" 3 "Barcode" ;
VAL_ 2332112278 M2I_Byrack_Enable_IMM21_06 1 "Deactive" 2 "Active" ;
VAL_ 2332112278 M2I_Byrack_ReVeEnable_IMM21_06 0 "invalid" 1 "Read SW-Version" 2 "Read HW-Version" 3 "Barcode" ;
VAL_ 2332112279 M2I_Byrack_Enable_IMM21_07 1 "Deactive" 2 "Active" ;
VAL_ 2332112279 M2I_Byrack_ReVeEnable_IMM21_07 0 "invalid" 1 "Read SW-Version" 2 "Read HW-Version" 3 "Barcode" ;
VAL_ 2332112280 M2I_Byrack_Enable_IMM21_08 1 "Deactive" 2 "Active" ;
VAL_ 2332112280 M2I_Byrack_ReVeEnable_IMM21_08 0 "invalid" 1 "Read SW-Version" 2 "Read HW-Version" 3 "Barcode" ;
VAL_ 2332112281 M2I_Byrack_Enable_IMM21_09 1 "Deactive" 2 "Active" ;
VAL_ 2332112281 M2I_Byrack_ReVeEnable_IMM21_09 0 "invalid" 1 "Read SW-Version" 2 "Read HW-Version" 3 "Barcode" ;
VAL_ 2332112282 M2I_Byrack_Enable_IMM21_10 1 "Deactive" 2 "Active" ;
VAL_ 2332112282 M2I_Byrack_ReVeEnable_IMM21_10 0 "invalid" 1 "Read SW-Version" 2 "Read HW-Version" 3 "Barcode" ;
VAL_ 2332112283 M2I_Byrack_Enable_IMM21_11 1 "Deactive" 2 "Active" ;
VAL_ 2332112283 M2I_Byrack_ReVeEnable_IMM21_11 0 "invalid" 1 "Read SW-Version" 2 "Read HW-Version" 3 "Barcode" ;
VAL_ 2332112284 M2I_Byrack_Enable_IMM21_12 1 "Deactive" 2 "Active" ;
VAL_ 2332112284 M2I_Byrack_ReVeEnable_IMM21_12 0 "invalid" 1 "Read SW-Version" 2 "Read HW-Version" 3 "Barcode" ;
VAL_ 2332112285 M2I_Byrack_Enable_IMM21_13 1 "Deactive" 2 "Active" ;
VAL_ 2332112285 M2I_Byrack_ReVeEnable_IMM21_13 0 "invalid" 1 "Read SW-Version" 2 "Read HW-Version" 3 "Barcode" ;
VAL_ 2332112286 M2I_Byrack_Enable_IMM21_14 1 "Deactive" 2 "Active" ;
VAL_ 2332112286 M2I_Byrack_ReVeEnable_IMM21_14 0 "invalid" 1 "Read SW-Version" 2 "Read HW-Version" 3 "Barcode" ;
VAL_ 2332112287 M2I_Byrack_Enable_IMM21_15 1 "Deactive" 2 "Active" ;
VAL_ 2332112287 M2I_Byrack_ReVeEnable_IMM21_15 0 "invalid" 1 "Read SW-Version" 2 "Read HW-Version" 3 "Barcode" ;
VAL_ 2332112288 M2I_Byrack_Enable_IMM21_16 1 "Deactive" 2 "Active" ;
VAL_ 2332112288 M2I_Byrack_ReVeEnable_IMM21_16 0 "invalid" 1 "Read SW-Version" 2 "Read HW-Version" 3 "Barcode" ;
VERSION ""

NS_ :

BS_:

BU_: MBMU PC SBMU IMM ETH DCDC LEMS

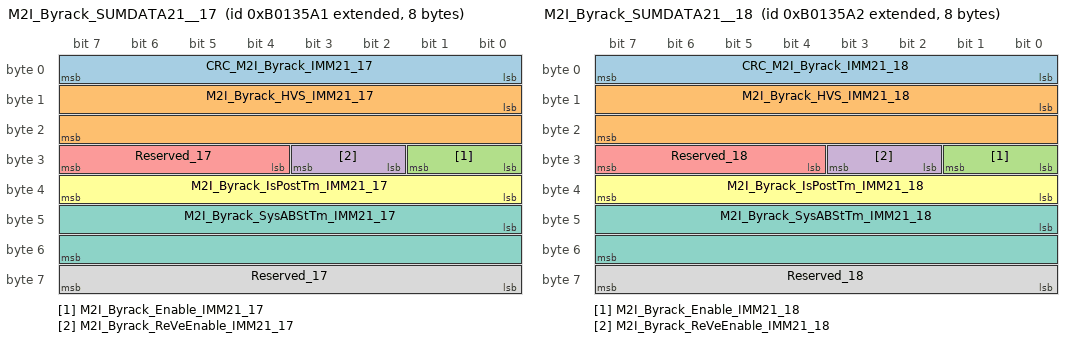
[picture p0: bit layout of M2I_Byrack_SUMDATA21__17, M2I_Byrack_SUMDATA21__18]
BO_ 2332112289 M2I_Byrack_SUMDATA21__17: 8 MBMU
 SG_ CRC_M2I_Byrack_IMM21_17 : 0|8@1+ (1,0) [0|255] ""  IMM
 SG_ M2I_Byrack_HVS_IMM21_17 : 8|16@1+ (0.1,0) [0|6553.5] "v"  IMM
 SG_ M2I_Byrack_Enable_IMM21_17 : 24|2@1+ (1,0) [0|3] ""  IMM
 SG_ M2I_Byrack_ReVeEnable_IMM21_17 : 26|2@1+ (1,0) [0|3] ""  IMM
 SG_ Reserved_17 : 28|4@1+ (1,0) [0|15] ""  IMM
 SG_ M2I_Byrack_IsPostTm_IMM21_17 : 32|8@1+ (0.01,0) [0|2.55] "s"  IMM
 SG_ M2I_Byrack_SysABStTm_IMM21_17 : 40|16@1+ (0.01,0) [0|655.35] "s"  IMM
 SG_ Reserved_17 : 56|8@1+ (1,0) [0|255] ""  IMM

BO_ 2332112290 M2I_Byrack_SUMDATA21__18: 8 MBMU
 SG_ CRC_M2I_Byrack_IMM21_18 : 0|8@1+ (1,0) [0|255] ""  IMM
 SG_ M2I_Byrack_HVS_IMM21_18 : 8|16@1+ (0.1,0) [0|6553.5] "v"  IMM
 SG_ M2I_Byrack_Enable_IMM21_18 : 24|2@1+ (1,0) [0|3] ""  IMM
 SG_ M2I_Byrack_ReVeEnable_IMM21_18 : 26|2@1+ (1,0) [0|3] ""  IMM
 SG_ Reserved_18 : 28|4@1+ (1,0) [0|15] ""  IMM
 SG_ M2I_Byrack_IsPostTm_IMM21_18 : 32|8@1+ (0.01,0) [0|2.55] "s"  IMM
 SG_ M2I_Byrack_SysABStTm_IMM21_18 : 40|16@1+ (0.01,0) [0|655.35] "s"  IMM
 SG_ Reserved_18 : 56|8@1+ (1,0) [0|255] ""  IMM

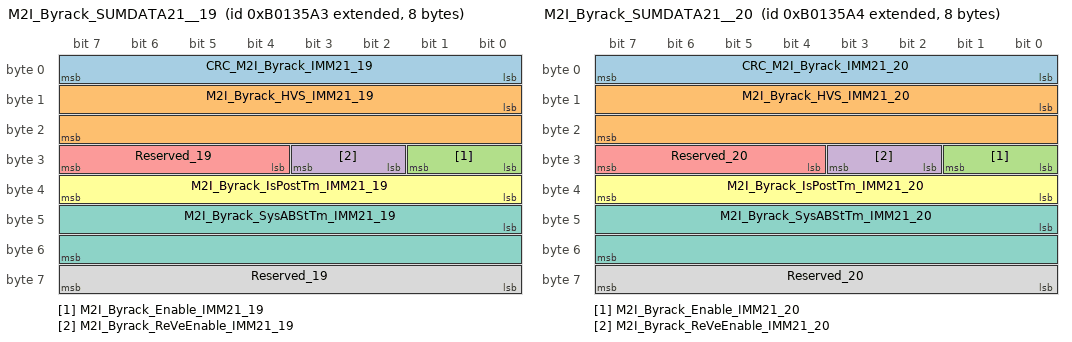
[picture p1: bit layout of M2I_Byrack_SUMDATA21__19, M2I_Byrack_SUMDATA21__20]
BO_ 2332112291 M2I_Byrack_SUMDATA21__19: 8 MBMU
 SG_ CRC_M2I_Byrack_IMM21_19 : 0|8@1+ (1,0) [0|255] ""  IMM
 SG_ M2I_Byrack_HVS_IMM21_19 : 8|16@1+ (0.1,0) [0|6553.5] "v"  IMM
 SG_ M2I_Byrack_Enable_IMM21_19 : 24|2@1+ (1,0) [0|3] ""  IMM
 SG_ M2I_Byrack_ReVeEnable_IMM21_19 : 26|2@1+ (1,0) [0|3] ""  IMM
 SG_ Reserved_19 : 28|4@1+ (1,0) [0|15] ""  IMM
 SG_ M2I_Byrack_IsPostTm_IMM21_19 : 32|8@1+ (0.01,0) [0|2.55] "s"  IMM
 SG_ M2I_Byrack_SysABStTm_IMM21_19 : 40|16@1+ (0.01,0) [0|655.35] "s"  IMM
 SG_ Reserved_19 : 56|8@1+ (1,0) [0|255] ""  IMM

BO_ 2332112292 M2I_Byrack_SUMDATA21__20: 8 MBMU
 SG_ CRC_M2I_Byrack_IMM21_20 : 0|8@1+ (1,0) [0|255] ""  IMM
 SG_ M2I_Byrack_HVS_IMM21_20 : 8|16@1+ (0.1,0) [0|6553.5] "v"  IMM
 SG_ M2I_Byrack_Enable_IMM21_20 : 24|2@1+ (1,0) [0|3] ""  IMM
 SG_ M2I_Byrack_ReVeEnable_IMM21_20 : 26|2@1+ (1,0) [0|3] ""  IMM
 SG_ Reserved_20 : 28|4@1+ (1,0) [0|15] ""  IMM
 SG_ M2I_Byrack_IsPostTm_IMM21_20 : 32|8@1+ (0.01,0) [0|2.55] "s"  IMM
 SG_ M2I_Byrack_SysABStTm_IMM21_20 : 40|16@1+ (0.01,0) [0|655.35] "s"  IMM
 SG_ Reserved_20 : 56|8@1+ (1,0) [0|255] ""  IMM

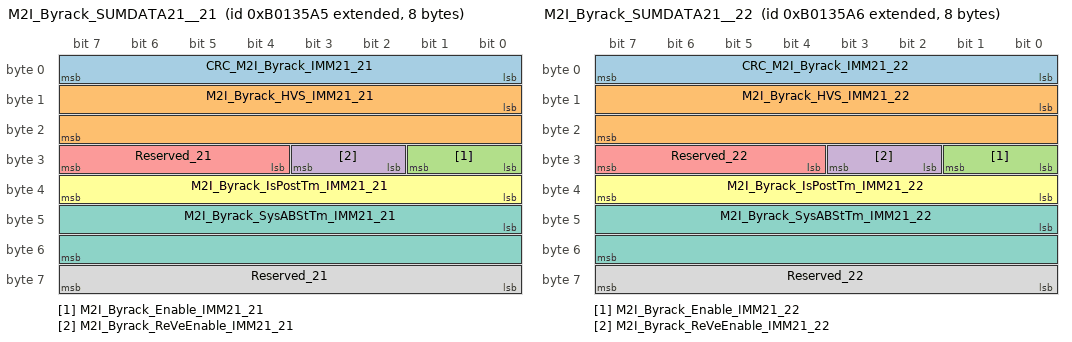
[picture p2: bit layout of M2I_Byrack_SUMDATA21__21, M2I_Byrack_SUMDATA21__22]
BO_ 2332112293 M2I_Byrack_SUMDATA21__21: 8 MBMU
 SG_ CRC_M2I_Byrack_IMM21_21 : 0|8@1+ (1,0) [0|255] ""  IMM
 SG_ M2I_Byrack_HVS_IMM21_21 : 8|16@1+ (0.1,0) [0|6553.5] "v"  IMM
 SG_ M2I_Byrack_Enable_IMM21_21 : 24|2@1+ (1,0) [0|3] ""  IMM
 SG_ M2I_Byrack_ReVeEnable_IMM21_21 : 26|2@1+ (1,0) [0|3] ""  IMM
 SG_ Reserved_21 : 28|4@1+ (1,0) [0|15] ""  IMM
 SG_ M2I_Byrack_IsPostTm_IMM21_21 : 32|8@1+ (0.01,0) [0|2.55] "s"  IMM
 SG_ M2I_Byrack_SysABStTm_IMM21_21 : 40|16@1+ (0.01,0) [0|655.35] "s"  IMM
 SG_ Reserved_21 : 56|8@1+ (1,0) [0|255] ""  IMM

BO_ 2332112294 M2I_Byrack_SUMDATA21__22: 8 MBMU
 SG_ CRC_M2I_Byrack_IMM21_22 : 0|8@1+ (1,0) [0|255] ""  IMM
 SG_ M2I_Byrack_HVS_IMM21_22 : 8|16@1+ (0.1,0) [0|6553.5] "v"  IMM
 SG_ M2I_Byrack_Enable_IMM21_22 : 24|2@1+ (1,0) [0|3] ""  IMM
 SG_ M2I_Byrack_ReVeEnable_IMM21_22 : 26|2@1+ (1,0) [0|3] ""  IMM
 SG_ Reserved_22 : 28|4@1+ (1,0) [0|15] ""  IMM
 SG_ M2I_Byrack_IsPostTm_IMM21_22 : 32|8@1+ (0.01,0) [0|2.55] "s"  IMM
 SG_ M2I_Byrack_SysABStTm_IMM21_22 : 40|16@1+ (0.01,0) [0|655.35] "s"  IMM
 SG_ Reserved_22 : 56|8@1+ (1,0) [0|255] ""  IMM

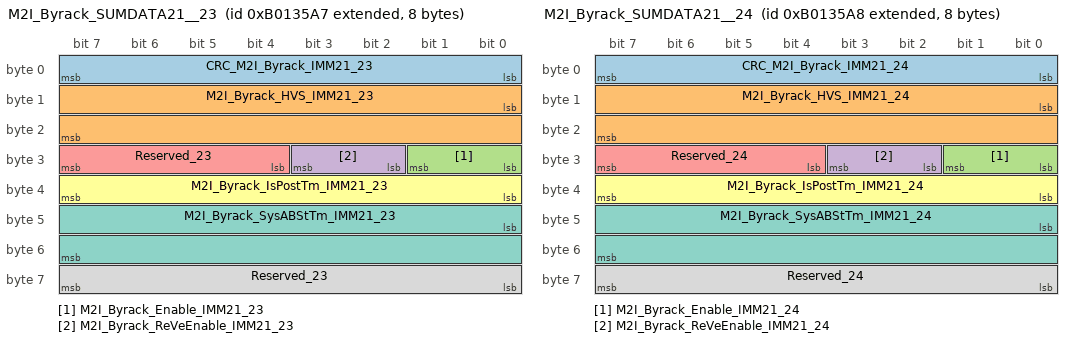
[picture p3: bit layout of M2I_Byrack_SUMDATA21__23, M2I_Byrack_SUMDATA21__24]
BO_ 2332112295 M2I_Byrack_SUMDATA21__23: 8 MBMU
 SG_ CRC_M2I_Byrack_IMM21_23 : 0|8@1+ (1,0) [0|255] ""  IMM
 SG_ M2I_Byrack_HVS_IMM21_23 : 8|16@1+ (0.1,0) [0|6553.5] "v"  IMM
 SG_ M2I_Byrack_Enable_IMM21_23 : 24|2@1+ (1,0) [0|3] ""  IMM
 SG_ M2I_Byrack_ReVeEnable_IMM21_23 : 26|2@1+ (1,0) [0|3] ""  IMM
 SG_ Reserved_23 : 28|4@1+ (1,0) [0|15] ""  IMM
 SG_ M2I_Byrack_IsPostTm_IMM21_23 : 32|8@1+ (0.01,0) [0|2.55] "s"  IMM
 SG_ M2I_Byrack_SysABStTm_IMM21_23 : 40|16@1+ (0.01,0) [0|655.35] "s"  IMM
 SG_ Reserved_23 : 56|8@1+ (1,0) [0|255] ""  IMM

BO_ 2332112296 M2I_Byrack_SUMDATA21__24: 8 MBMU
 SG_ CRC_M2I_Byrack_IMM21_24 : 0|8@1+ (1,0) [0|255] ""  IMM
 SG_ M2I_Byrack_HVS_IMM21_24 : 8|16@1+ (0.1,0) [0|6553.5] "v"  IMM
 SG_ M2I_Byrack_Enable_IMM21_24 : 24|2@1+ (1,0) [0|3] ""  IMM
 SG_ M2I_Byrack_ReVeEnable_IMM21_24 : 26|2@1+ (1,0) [0|3] ""  IMM
 SG_ Reserved_24 : 28|4@1+ (1,0) [0|15] ""  IMM
 SG_ M2I_Byrack_IsPostTm_IMM21_24 : 32|8@1+ (0.01,0) [0|2.55] "s"  IMM
 SG_ M2I_Byrack_SysABStTm_IMM21_24 : 40|16@1+ (0.01,0) [0|655.35] "s"  IMM
 SG_ Reserved_24 : 56|8@1+ (1,0) [0|255] ""  IMM

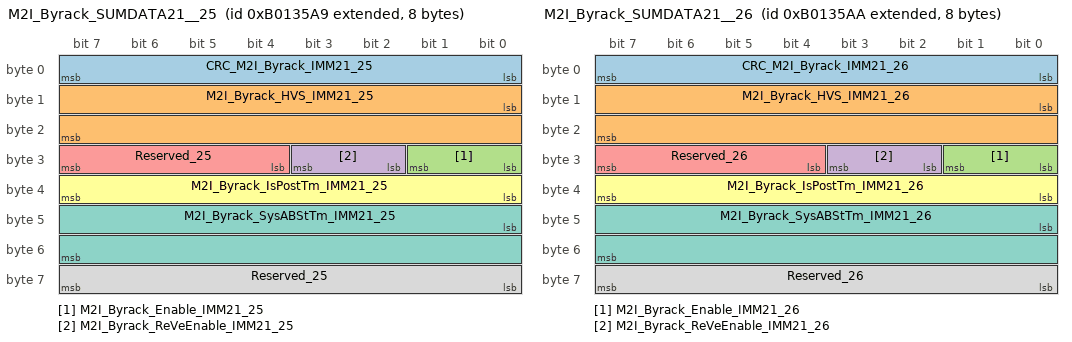
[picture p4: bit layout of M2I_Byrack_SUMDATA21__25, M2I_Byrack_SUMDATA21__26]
BO_ 2332112297 M2I_Byrack_SUMDATA21__25: 8 MBMU
 SG_ CRC_M2I_Byrack_IMM21_25 : 0|8@1+ (1,0) [0|255] ""  IMM
 SG_ M2I_Byrack_HVS_IMM21_25 : 8|16@1+ (0.1,0) [0|6553.5] "v"  IMM
 SG_ M2I_Byrack_Enable_IMM21_25 : 24|2@1+ (1,0) [0|3] ""  IMM
 SG_ M2I_Byrack_ReVeEnable_IMM21_25 : 26|2@1+ (1,0) [0|3] ""  IMM
 SG_ Reserved_25 : 28|4@1+ (1,0) [0|15] ""  IMM
 SG_ M2I_Byrack_IsPostTm_IMM21_25 : 32|8@1+ (0.01,0) [0|2.55] "s"  IMM
 SG_ M2I_Byrack_SysABStTm_IMM21_25 : 40|16@1+ (0.01,0) [0|655.35] "s"  IMM
 SG_ Reserved_25 : 56|8@1+ (1,0) [0|255] ""  IMM

BO_ 2332112298 M2I_Byrack_SUMDATA21__26: 8 MBMU
 SG_ CRC_M2I_Byrack_IMM21_26 : 0|8@1+ (1,0) [0|255] ""  IMM
 SG_ M2I_Byrack_HVS_IMM21_26 : 8|16@1+ (0.1,0) [0|6553.5] "v"  IMM
 SG_ M2I_Byrack_Enable_IMM21_26 : 24|2@1+ (1,0) [0|3] ""  IMM
 SG_ M2I_Byrack_ReVeEnable_IMM21_26 : 26|2@1+ (1,0) [0|3] ""  IMM
 SG_ Reserved_26 : 28|4@1+ (1,0) [0|15] ""  IMM
 SG_ M2I_Byrack_IsPostTm_IMM21_26 : 32|8@1+ (0.01,0) [0|2.55] "s"  IMM
 SG_ M2I_Byrack_SysABStTm_IMM21_26 : 40|16@1+ (0.01,0) [0|655.35] "s"  IMM
 SG_ Reserved_26 : 56|8@1+ (1,0) [0|255] ""  IMM

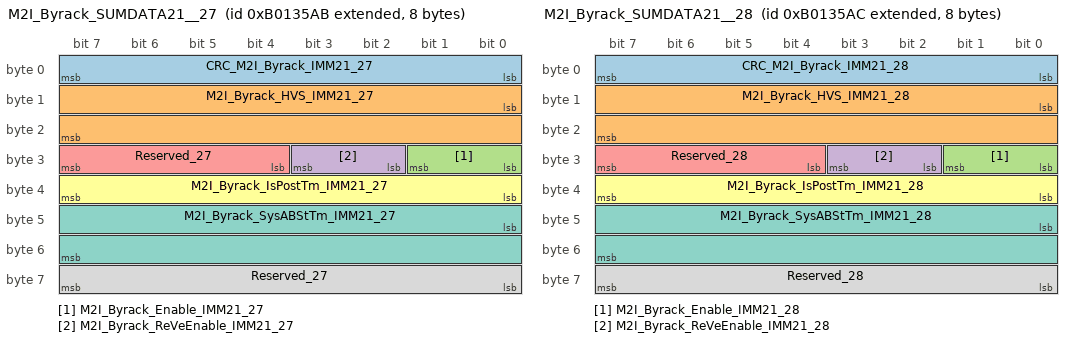
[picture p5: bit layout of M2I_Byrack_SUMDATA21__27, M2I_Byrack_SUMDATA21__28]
BO_ 2332112299 M2I_Byrack_SUMDATA21__27: 8 MBMU
 SG_ CRC_M2I_Byrack_IMM21_27 : 0|8@1+ (1,0) [0|255] ""  IMM
 SG_ M2I_Byrack_HVS_IMM21_27 : 8|16@1+ (0.1,0) [0|6553.5] "v"  IMM
 SG_ M2I_Byrack_Enable_IMM21_27 : 24|2@1+ (1,0) [0|3] ""  IMM
 SG_ M2I_Byrack_ReVeEnable_IMM21_27 : 26|2@1+ (1,0) [0|3] ""  IMM
 SG_ Reserved_27 : 28|4@1+ (1,0) [0|15] ""  IMM
 SG_ M2I_Byrack_IsPostTm_IMM21_27 : 32|8@1+ (0.01,0) [0|2.55] "s"  IMM
 SG_ M2I_Byrack_SysABStTm_IMM21_27 : 40|16@1+ (0.01,0) [0|655.35] "s"  IMM
 SG_ Reserved_27 : 56|8@1+ (1,0) [0|255] ""  IMM

BO_ 2332112300 M2I_Byrack_SUMDATA21__28: 8 MBMU
 SG_ CRC_M2I_Byrack_IMM21_28 : 0|8@1+ (1,0) [0|255] ""  IMM
 SG_ M2I_Byrack_HVS_IMM21_28 : 8|16@1+ (0.1,0) [0|6553.5] "v"  IMM
 SG_ M2I_Byrack_Enable_IMM21_28 : 24|2@1+ (1,0) [0|3] ""  IMM
 SG_ M2I_Byrack_ReVeEnable_IMM21_28 : 26|2@1+ (1,0) [0|3] ""  IMM
 SG_ Reserved_28 : 28|4@1+ (1,0) [0|15] ""  IMM
 SG_ M2I_Byrack_IsPostTm_IMM21_28 : 32|8@1+ (0.01,0) [0|2.55] "s"  IMM
 SG_ M2I_Byrack_SysABStTm_IMM21_28 : 40|16@1+ (0.01,0) [0|655.35] "s"  IMM
 SG_ Reserved_28 : 56|8@1+ (1,0) [0|255] ""  IMM

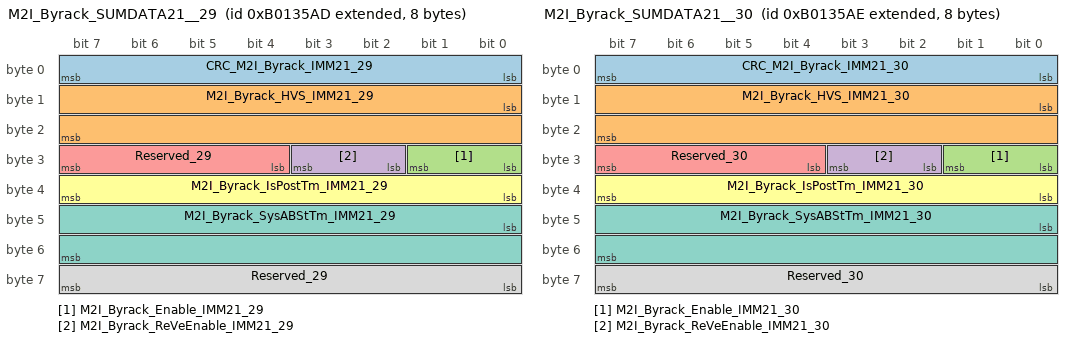
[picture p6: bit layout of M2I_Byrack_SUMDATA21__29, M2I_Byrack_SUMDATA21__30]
BO_ 2332112301 M2I_Byrack_SUMDATA21__29: 8 MBMU
 SG_ CRC_M2I_Byrack_IMM21_29 : 0|8@1+ (1,0) [0|255] ""  IMM
 SG_ M2I_Byrack_HVS_IMM21_29 : 8|16@1+ (0.1,0) [0|6553.5] "v"  IMM
 SG_ M2I_Byrack_Enable_IMM21_29 : 24|2@1+ (1,0) [0|3] ""  IMM
 SG_ M2I_Byrack_ReVeEnable_IMM21_29 : 26|2@1+ (1,0) [0|3] ""  IMM
 SG_ Reserved_29 : 28|4@1+ (1,0) [0|15] ""  IMM
 SG_ M2I_Byrack_IsPostTm_IMM21_29 : 32|8@1+ (0.01,0) [0|2.55] "s"  IMM
 SG_ M2I_Byrack_SysABStTm_IMM21_29 : 40|16@1+ (0.01,0) [0|655.35] "s"  IMM
 SG_ Reserved_29 : 56|8@1+ (1,0) [0|255] ""  IMM

BO_ 2332112302 M2I_Byrack_SUMDATA21__30: 8 MBMU
 SG_ CRC_M2I_Byrack_IMM21_30 : 0|8@1+ (1,0) [0|255] ""  IMM
 SG_ M2I_Byrack_HVS_IMM21_30 : 8|16@1+ (0.1,0) [0|6553.5] "v"  IMM
 SG_ M2I_Byrack_Enable_IMM21_30 : 24|2@1+ (1,0) [0|3] ""  IMM
 SG_ M2I_Byrack_ReVeEnable_IMM21_30 : 26|2@1+ (1,0) [0|3] ""  IMM
 SG_ Reserved_30 : 28|4@1+ (1,0) [0|15] ""  IMM
 SG_ M2I_Byrack_IsPostTm_IMM21_30 : 32|8@1+ (0.01,0) [0|2.55] "s"  IMM
 SG_ M2I_Byrack_SysABStTm_IMM21_30 : 40|16@1+ (0.01,0) [0|655.35] "s"  IMM
 SG_ Reserved_30 : 56|8@1+ (1,0) [0|255] ""  IMM

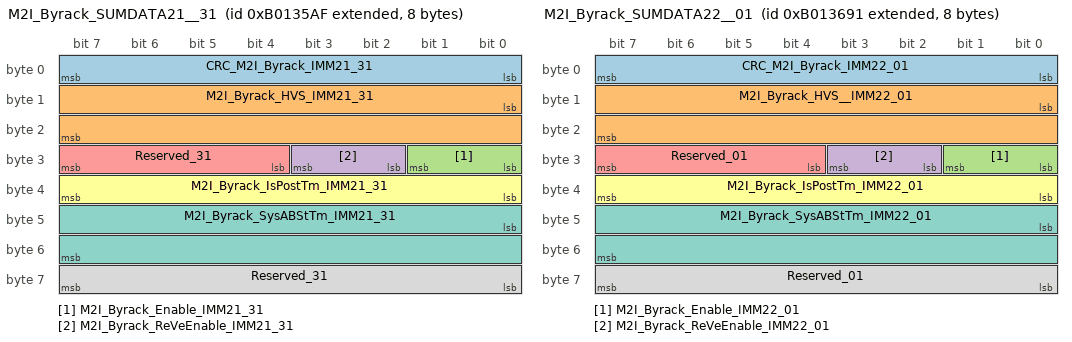
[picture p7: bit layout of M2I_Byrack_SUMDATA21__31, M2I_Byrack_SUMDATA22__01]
BO_ 2332112303 M2I_Byrack_SUMDATA21__31: 8 MBMU
 SG_ CRC_M2I_Byrack_IMM21_31 : 0|8@1+ (1,0) [0|255] ""  IMM
 SG_ M2I_Byrack_HVS_IMM21_31 : 8|16@1+ (0.1,0) [0|6553.5] "v"  IMM
 SG_ M2I_Byrack_Enable_IMM21_31 : 24|2@1+ (1,0) [0|3] ""  IMM
 SG_ M2I_Byrack_ReVeEnable_IMM21_31 : 26|2@1+ (1,0) [0|3] ""  IMM
 SG_ Reserved_31 : 28|4@1+ (1,0) [0|15] ""  IMM
 SG_ M2I_Byrack_IsPostTm_IMM21_31 : 32|8@1+ (0.01,0) [0|2.55] "s"  IMM
 SG_ M2I_Byrack_SysABStTm_IMM21_31 : 40|16@1+ (0.01,0) [0|655.35] "s"  IMM
 SG_ Reserved_31 : 56|8@1+ (1,0) [0|255] ""  IMM

BO_ 2332112529 M2I_Byrack_SUMDATA22__01: 8 MBMU
 SG_ CRC_M2I_Byrack_IMM22_01 : 0|8@1+ (1,0) [0|255] ""  IMM
 SG_ M2I_Byrack_HVS__IMM22_01 : 8|16@1+ (0.1,0) [0|6553.5] "v"  IMM
 SG_ M2I_Byrack_Enable_IMM22_01 : 24|2@1+ (1,0) [0|3] ""  IMM
 SG_ M2I_Byrack_ReVeEnable_IMM22_01 : 26|2@1+ (1,0) [0|3] ""  IMM
 SG_ Reserved_01 : 28|4@1+ (1,0) [0|15] ""  IMM
 SG_ M2I_Byrack_IsPostTm_IMM22_01 : 32|8@1+ (0.01,0) [0|2.55] "s"  IMM
 SG_ M2I_Byrack_SysABStTm_IMM22_01 : 40|16@1+ (0.01,0) [0|655.35] "s"  IMM
 SG_ Reserved_01 : 56|8@1+ (1,0) [0|255] ""  IMM

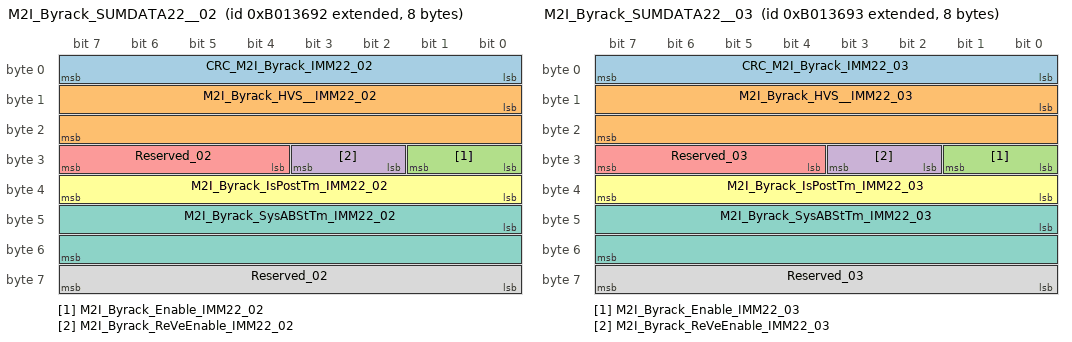
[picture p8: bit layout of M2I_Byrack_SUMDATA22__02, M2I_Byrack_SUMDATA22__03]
BO_ 2332112530 M2I_Byrack_SUMDATA22__02: 8 MBMU
 SG_ CRC_M2I_Byrack_IMM22_02 : 0|8@1+ (1,0) [0|255] ""  IMM
 SG_ M2I_Byrack_HVS__IMM22_02 : 8|16@1+ (0.1,0) [0|6553.5] "v"  IMM
 SG_ M2I_Byrack_Enable_IMM22_02 : 24|2@1+ (1,0) [0|3] ""  IMM
 SG_ M2I_Byrack_ReVeEnable_IMM22_02 : 26|2@1+ (1,0) [0|3] ""  IMM
 SG_ Reserved_02 : 28|4@1+ (1,0) [0|15] ""  IMM
 SG_ M2I_Byrack_IsPostTm_IMM22_02 : 32|8@1+ (0.01,0) [0|2.55] "s"  IMM
 SG_ M2I_Byrack_SysABStTm_IMM22_02 : 40|16@1+ (0.01,0) [0|655.35] "s"  IMM
 SG_ Reserved_02 : 56|8@1+ (1,0) [0|255] ""  IMM

BO_ 2332112531 M2I_Byrack_SUMDATA22__03: 8 MBMU
 SG_ CRC_M2I_Byrack_IMM22_03 : 0|8@1+ (1,0) [0|255] ""  IMM
 SG_ M2I_Byrack_HVS__IMM22_03 : 8|16@1+ (0.1,0) [0|6553.5] "v"  IMM
 SG_ M2I_Byrack_Enable_IMM22_03 : 24|2@1+ (1,0) [0|3] ""  IMM
 SG_ M2I_Byrack_ReVeEnable_IMM22_03 : 26|2@1+ (1,0) [0|3] ""  IMM
 SG_ Reserved_03 : 28|4@1+ (1,0) [0|15] ""  IMM
 SG_ M2I_Byrack_IsPostTm_IMM22_03 : 32|8@1+ (0.01,0) [0|2.55] "s"  IMM
 SG_ M2I_Byrack_SysABStTm_IMM22_03 : 40|16@1+ (0.01,0) [0|655.35] "s"  IMM
 SG_ Reserved_03 : 56|8@1+ (1,0) [0|255] ""  IMM

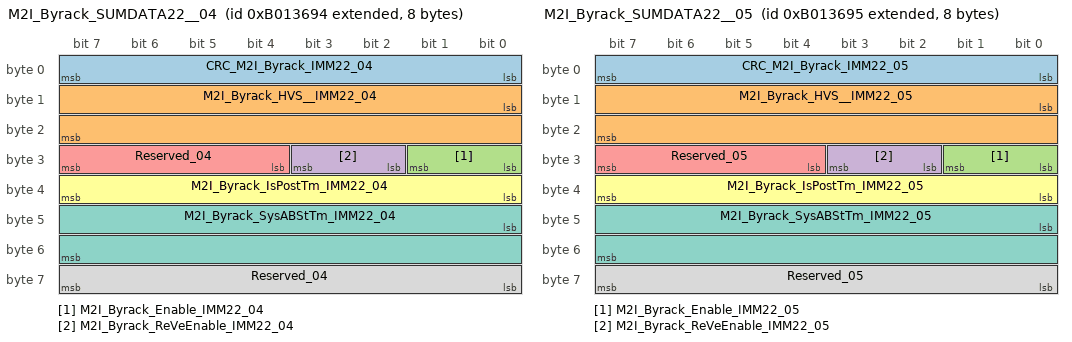
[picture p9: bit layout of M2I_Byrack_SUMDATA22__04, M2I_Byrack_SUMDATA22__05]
BO_ 2332112532 M2I_Byrack_SUMDATA22__04: 8 MBMU
 SG_ CRC_M2I_Byrack_IMM22_04 : 0|8@1+ (1,0) [0|255] ""  IMM
 SG_ M2I_Byrack_HVS__IMM22_04 : 8|16@1+ (0.1,0) [0|6553.5] "v"  IMM
 SG_ M2I_Byrack_Enable_IMM22_04 : 24|2@1+ (1,0) [0|3] ""  IMM
 SG_ M2I_Byrack_ReVeEnable_IMM22_04 : 26|2@1+ (1,0) [0|3] ""  IMM
 SG_ Reserved_04 : 28|4@1+ (1,0) [0|15] ""  IMM
 SG_ M2I_Byrack_IsPostTm_IMM22_04 : 32|8@1+ (0.01,0) [0|2.55] "s"  IMM
 SG_ M2I_Byrack_SysABStTm_IMM22_04 : 40|16@1+ (0.01,0) [0|655.35] "s"  IMM
 SG_ Reserved_04 : 56|8@1+ (1,0) [0|255] ""  IMM

BO_ 2332112533 M2I_Byrack_SUMDATA22__05: 8 MBMU
 SG_ CRC_M2I_Byrack_IMM22_05 : 0|8@1+ (1,0) [0|255] ""  IMM
 SG_ M2I_Byrack_HVS__IMM22_05 : 8|16@1+ (0.1,0) [0|6553.5] "v"  IMM
 SG_ M2I_Byrack_Enable_IMM22_05 : 24|2@1+ (1,0) [0|3] ""  IMM
 SG_ M2I_Byrack_ReVeEnable_IMM22_05 : 26|2@1+ (1,0) [0|3] ""  IMM
 SG_ Reserved_05 : 28|4@1+ (1,0) [0|15] ""  IMM
 SG_ M2I_Byrack_IsPostTm_IMM22_05 : 32|8@1+ (0.01,0) [0|2.55] "s"  IMM
 SG_ M2I_Byrack_SysABStTm_IMM22_05 : 40|16@1+ (0.01,0) [0|655.35] "s"  IMM
 SG_ Reserved_05 : 56|8@1+ (1,0) [0|255] ""  IMM

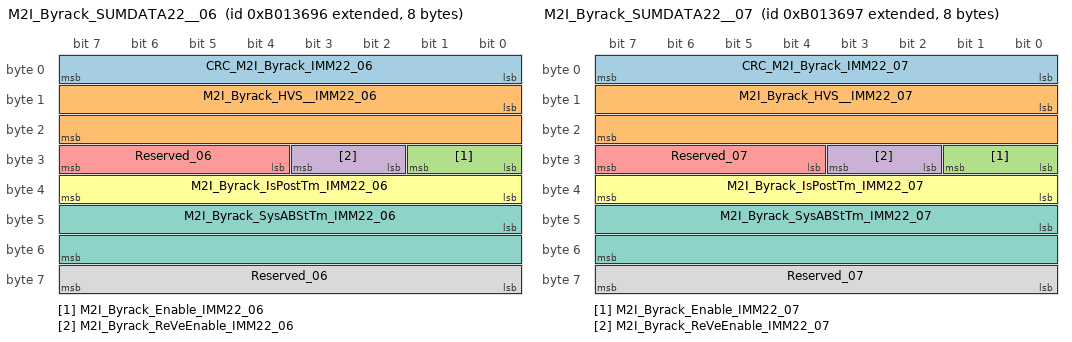
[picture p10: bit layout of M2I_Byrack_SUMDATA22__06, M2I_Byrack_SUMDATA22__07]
BO_ 2332112534 M2I_Byrack_SUMDATA22__06: 8 MBMU
 SG_ CRC_M2I_Byrack_IMM22_06 : 0|8@1+ (1,0) [0|255] ""  IMM
 SG_ M2I_Byrack_HVS__IMM22_06 : 8|16@1+ (0.1,0) [0|6553.5] "v"  IMM
 SG_ M2I_Byrack_Enable_IMM22_06 : 24|2@1+ (1,0) [0|3] ""  IMM
 SG_ M2I_Byrack_ReVeEnable_IMM22_06 : 26|2@1+ (1,0) [0|3] ""  IMM
 SG_ Reserved_06 : 28|4@1+ (1,0) [0|15] ""  IMM
 SG_ M2I_Byrack_IsPostTm_IMM22_06 : 32|8@1+ (0.01,0) [0|2.55] "s"  IMM
 SG_ M2I_Byrack_SysABStTm_IMM22_06 : 40|16@1+ (0.01,0) [0|655.35] "s"  IMM
 SG_ Reserved_06 : 56|8@1+ (1,0) [0|255] ""  IMM

BO_ 2332112535 M2I_Byrack_SUMDATA22__07: 8 MBMU
 SG_ CRC_M2I_Byrack_IMM22_07 : 0|8@1+ (1,0) [0|255] ""  IMM
 SG_ M2I_Byrack_HVS__IMM22_07 : 8|16@1+ (0.1,0) [0|6553.5] "v"  IMM
 SG_ M2I_Byrack_Enable_IMM22_07 : 24|2@1+ (1,0) [0|3] ""  IMM
 SG_ M2I_Byrack_ReVeEnable_IMM22_07 : 26|2@1+ (1,0) [0|3] ""  IMM
 SG_ Reserved_07 : 28|4@1+ (1,0) [0|15] ""  IMM
 SG_ M2I_Byrack_IsPostTm_IMM22_07 : 32|8@1+ (0.01,0) [0|2.55] "s"  IMM
 SG_ M2I_Byrack_SysABStTm_IMM22_07 : 40|16@1+ (0.01,0) [0|655.35] "s"  IMM
 SG_ Reserved_07 : 56|8@1+ (1,0) [0|255] ""  IMM

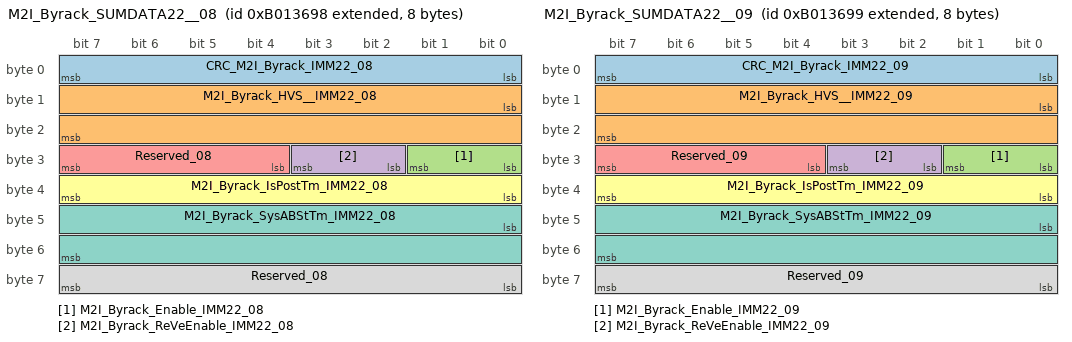
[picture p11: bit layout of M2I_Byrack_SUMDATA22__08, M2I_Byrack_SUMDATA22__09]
BO_ 2332112536 M2I_Byrack_SUMDATA22__08: 8 MBMU
 SG_ CRC_M2I_Byrack_IMM22_08 : 0|8@1+ (1,0) [0|255] ""  IMM
 SG_ M2I_Byrack_HVS__IMM22_08 : 8|16@1+ (0.1,0) [0|6553.5] "v"  IMM
 SG_ M2I_Byrack_Enable_IMM22_08 : 24|2@1+ (1,0) [0|3] ""  IMM
 SG_ M2I_Byrack_ReVeEnable_IMM22_08 : 26|2@1+ (1,0) [0|3] ""  IMM
 SG_ Reserved_08 : 28|4@1+ (1,0) [0|15] ""  IMM
 SG_ M2I_Byrack_IsPostTm_IMM22_08 : 32|8@1+ (0.01,0) [0|2.55] "s"  IMM
 SG_ M2I_Byrack_SysABStTm_IMM22_08 : 40|16@1+ (0.01,0) [0|655.35] "s"  IMM
 SG_ Reserved_08 : 56|8@1+ (1,0) [0|255] ""  IMM

BO_ 2332112537 M2I_Byrack_SUMDATA22__09: 8 MBMU
 SG_ CRC_M2I_Byrack_IMM22_09 : 0|8@1+ (1,0) [0|255] ""  IMM
 SG_ M2I_Byrack_HVS__IMM22_09 : 8|16@1+ (0.1,0) [0|6553.5] "v"  IMM
 SG_ M2I_Byrack_Enable_IMM22_09 : 24|2@1+ (1,0) [0|3] ""  IMM
 SG_ M2I_Byrack_ReVeEnable_IMM22_09 : 26|2@1+ (1,0) [0|3] ""  IMM
 SG_ Reserved_09 : 28|4@1+ (1,0) [0|15] ""  IMM
 SG_ M2I_Byrack_IsPostTm_IMM22_09 : 32|8@1+ (0.01,0) [0|2.55] "s"  IMM
 SG_ M2I_Byrack_SysABStTm_IMM22_09 : 40|16@1+ (0.01,0) [0|655.35] "s"  IMM
 SG_ Reserved_09 : 56|8@1+ (1,0) [0|255] ""  IMM

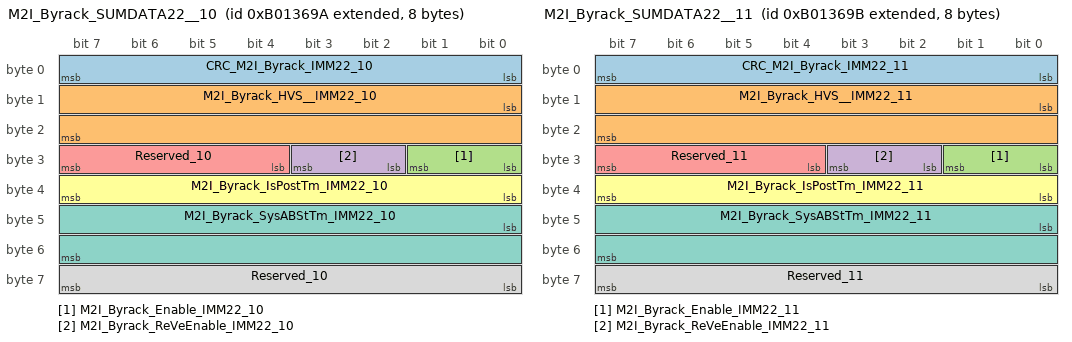
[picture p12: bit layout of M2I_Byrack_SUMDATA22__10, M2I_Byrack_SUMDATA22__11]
BO_ 2332112538 M2I_Byrack_SUMDATA22__10: 8 MBMU
 SG_ CRC_M2I_Byrack_IMM22_10 : 0|8@1+ (1,0) [0|255] ""  IMM
 SG_ M2I_Byrack_HVS__IMM22_10 : 8|16@1+ (0.1,0) [0|6553.5] "v"  IMM
 SG_ M2I_Byrack_Enable_IMM22_10 : 24|2@1+ (1,0) [0|3] ""  IMM
 SG_ M2I_Byrack_ReVeEnable_IMM22_10 : 26|2@1+ (1,0) [0|3] ""  IMM
 SG_ Reserved_10 : 28|4@1+ (1,0) [0|15] ""  IMM
 SG_ M2I_Byrack_IsPostTm_IMM22_10 : 32|8@1+ (0.01,0) [0|2.55] "s"  IMM
 SG_ M2I_Byrack_SysABStTm_IMM22_10 : 40|16@1+ (0.01,0) [0|655.35] "s"  IMM
 SG_ Reserved_10 : 56|8@1+ (1,0) [0|255] ""  IMM

BO_ 2332112539 M2I_Byrack_SUMDATA22__11: 8 MBMU
 SG_ CRC_M2I_Byrack_IMM22_11 : 0|8@1+ (1,0) [0|255] ""  IMM
 SG_ M2I_Byrack_HVS__IMM22_11 : 8|16@1+ (0.1,0) [0|6553.5] "v"  IMM
 SG_ M2I_Byrack_Enable_IMM22_11 : 24|2@1+ (1,0) [0|3] ""  IMM
 SG_ M2I_Byrack_ReVeEnable_IMM22_11 : 26|2@1+ (1,0) [0|3] ""  IMM
 SG_ Reserved_11 : 28|4@1+ (1,0) [0|15] ""  IMM
 SG_ M2I_Byrack_IsPostTm_IMM22_11 : 32|8@1+ (0.01,0) [0|2.55] "s"  IMM
 SG_ M2I_Byrack_SysABStTm_IMM22_11 : 40|16@1+ (0.01,0) [0|655.35] "s"  IMM
 SG_ Reserved_11 : 56|8@1+ (1,0) [0|255] ""  IMM

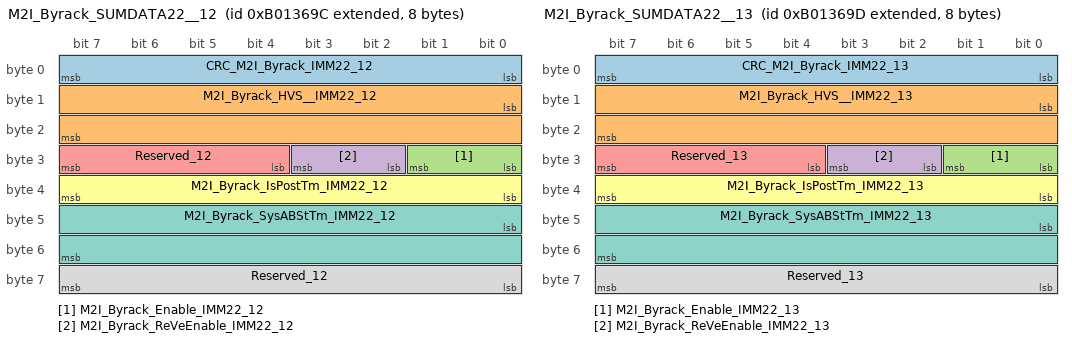
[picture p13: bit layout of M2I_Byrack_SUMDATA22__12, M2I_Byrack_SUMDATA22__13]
BO_ 2332112540 M2I_Byrack_SUMDATA22__12: 8 MBMU
 SG_ CRC_M2I_Byrack_IMM22_12 : 0|8@1+ (1,0) [0|255] ""  IMM
 SG_ M2I_Byrack_HVS__IMM22_12 : 8|16@1+ (0.1,0) [0|6553.5] "v"  IMM
 SG_ M2I_Byrack_Enable_IMM22_12 : 24|2@1+ (1,0) [0|3] ""  IMM
 SG_ M2I_Byrack_ReVeEnable_IMM22_12 : 26|2@1+ (1,0) [0|3] ""  IMM
 SG_ Reserved_12 : 28|4@1+ (1,0) [0|15] ""  IMM
 SG_ M2I_Byrack_IsPostTm_IMM22_12 : 32|8@1+ (0.01,0) [0|2.55] "s"  IMM
 SG_ M2I_Byrack_SysABStTm_IMM22_12 : 40|16@1+ (0.01,0) [0|655.35] "s"  IMM
 SG_ Reserved_12 : 56|8@1+ (1,0) [0|255] ""  IMM

BO_ 2332112541 M2I_Byrack_SUMDATA22__13: 8 MBMU
 SG_ CRC_M2I_Byrack_IMM22_13 : 0|8@1+ (1,0) [0|255] ""  IMM
 SG_ M2I_Byrack_HVS__IMM22_13 : 8|16@1+ (0.1,0) [0|6553.5] "v"  IMM
 SG_ M2I_Byrack_Enable_IMM22_13 : 24|2@1+ (1,0) [0|3] ""  IMM
 SG_ M2I_Byrack_ReVeEnable_IMM22_13 : 26|2@1+ (1,0) [0|3] ""  IMM
 SG_ Reserved_13 : 28|4@1+ (1,0) [0|15] ""  IMM
 SG_ M2I_Byrack_IsPostTm_IMM22_13 : 32|8@1+ (0.01,0) [0|2.55] "s"  IMM
 SG_ M2I_Byrack_SysABStTm_IMM22_13 : 40|16@1+ (0.01,0) [0|655.35] "s"  IMM
 SG_ Reserved_13 : 56|8@1+ (1,0) [0|255] ""  IMM

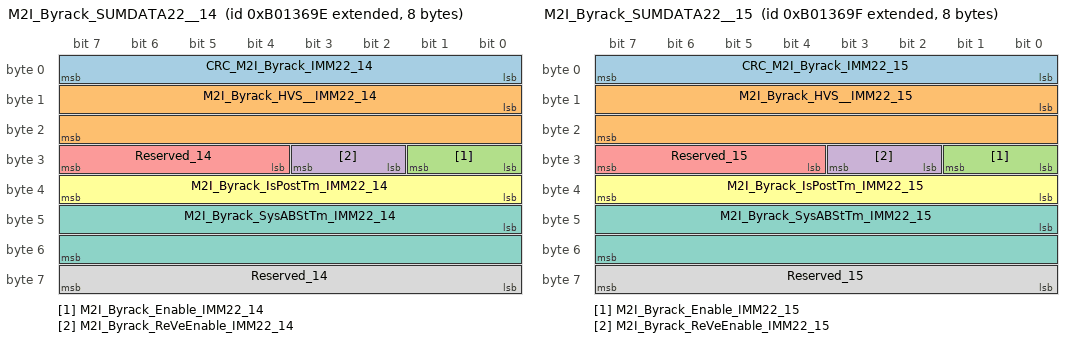
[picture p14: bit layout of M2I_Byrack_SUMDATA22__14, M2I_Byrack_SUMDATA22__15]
BO_ 2332112542 M2I_Byrack_SUMDATA22__14: 8 MBMU
 SG_ CRC_M2I_Byrack_IMM22_14 : 0|8@1+ (1,0) [0|255] ""  IMM
 SG_ M2I_Byrack_HVS__IMM22_14 : 8|16@1+ (0.1,0) [0|6553.5] "v"  IMM
 SG_ M2I_Byrack_Enable_IMM22_14 : 24|2@1+ (1,0) [0|3] ""  IMM
 SG_ M2I_Byrack_ReVeEnable_IMM22_14 : 26|2@1+ (1,0) [0|3] ""  IMM
 SG_ Reserved_14 : 28|4@1+ (1,0) [0|15] ""  IMM
 SG_ M2I_Byrack_IsPostTm_IMM22_14 : 32|8@1+ (0.01,0) [0|2.55] "s"  IMM
 SG_ M2I_Byrack_SysABStTm_IMM22_14 : 40|16@1+ (0.01,0) [0|655.35] "s"  IMM
 SG_ Reserved_14 : 56|8@1+ (1,0) [0|255] ""  IMM

BO_ 2332112543 M2I_Byrack_SUMDATA22__15: 8 MBMU
 SG_ CRC_M2I_Byrack_IMM22_15 : 0|8@1+ (1,0) [0|255] ""  IMM
 SG_ M2I_Byrack_HVS__IMM22_15 : 8|16@1+ (0.1,0) [0|6553.5] "v"  IMM
 SG_ M2I_Byrack_Enable_IMM22_15 : 24|2@1+ (1,0) [0|3] ""  IMM
 SG_ M2I_Byrack_ReVeEnable_IMM22_15 : 26|2@1+ (1,0) [0|3] ""  IMM
 SG_ Reserved_15 : 28|4@1+ (1,0) [0|15] ""  IMM
 SG_ M2I_Byrack_IsPostTm_IMM22_15 : 32|8@1+ (0.01,0) [0|2.55] "s"  IMM
 SG_ M2I_Byrack_SysABStTm_IMM22_15 : 40|16@1+ (0.01,0) [0|655.35] "s"  IMM
 SG_ Reserved_15 : 56|8@1+ (1,0) [0|255] ""  IMM

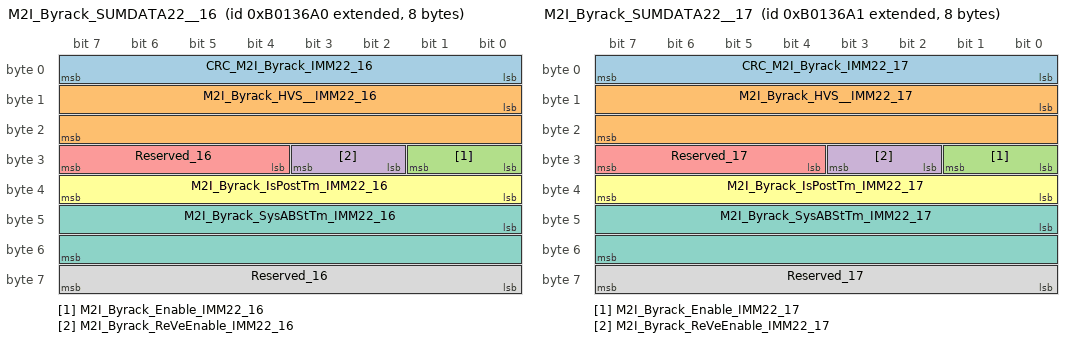
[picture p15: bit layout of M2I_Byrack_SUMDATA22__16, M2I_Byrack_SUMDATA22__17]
BO_ 2332112544 M2I_Byrack_SUMDATA22__16: 8 MBMU
 SG_ CRC_M2I_Byrack_IMM22_16 : 0|8@1+ (1,0) [0|255] ""  IMM
 SG_ M2I_Byrack_HVS__IMM22_16 : 8|16@1+ (0.1,0) [0|6553.5] "v"  IMM
 SG_ M2I_Byrack_Enable_IMM22_16 : 24|2@1+ (1,0) [0|3] ""  IMM
 SG_ M2I_Byrack_ReVeEnable_IMM22_16 : 26|2@1+ (1,0) [0|3] ""  IMM
 SG_ Reserved_16 : 28|4@1+ (1,0) [0|15] ""  IMM
 SG_ M2I_Byrack_IsPostTm_IMM22_16 : 32|8@1+ (0.01,0) [0|2.55] "s"  IMM
 SG_ M2I_Byrack_SysABStTm_IMM22_16 : 40|16@1+ (0.01,0) [0|655.35] "s"  IMM
 SG_ Reserved_16 : 56|8@1+ (1,0) [0|255] ""  IMM

BO_ 2332112545 M2I_Byrack_SUMDATA22__17: 8 MBMU
 SG_ CRC_M2I_Byrack_IMM22_17 : 0|8@1+ (1,0) [0|255] ""  IMM
 SG_ M2I_Byrack_HVS__IMM22_17 : 8|16@1+ (0.1,0) [0|6553.5] "v"  IMM
 SG_ M2I_Byrack_Enable_IMM22_17 : 24|2@1+ (1,0) [0|3] ""  IMM
 SG_ M2I_Byrack_ReVeEnable_IMM22_17 : 26|2@1+ (1,0) [0|3] ""  IMM
 SG_ Reserved_17 : 28|4@1+ (1,0) [0|15] ""  IMM
 SG_ M2I_Byrack_IsPostTm_IMM22_17 : 32|8@1+ (0.01,0) [0|2.55] "s"  IMM
 SG_ M2I_Byrack_SysABStTm_IMM22_17 : 40|16@1+ (0.01,0) [0|655.35] "s"  IMM
 SG_ Reserved_17 : 56|8@1+ (1,0) [0|255] ""  IMM

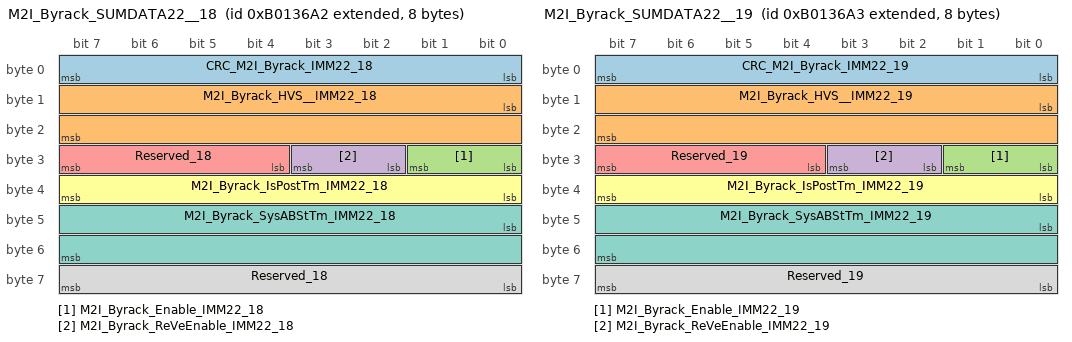
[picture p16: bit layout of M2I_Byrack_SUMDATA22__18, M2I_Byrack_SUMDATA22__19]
BO_ 2332112546 M2I_Byrack_SUMDATA22__18: 8 MBMU
 SG_ CRC_M2I_Byrack_IMM22_18 : 0|8@1+ (1,0) [0|255] ""  IMM
 SG_ M2I_Byrack_HVS__IMM22_18 : 8|16@1+ (0.1,0) [0|6553.5] "v"  IMM
 SG_ M2I_Byrack_Enable_IMM22_18 : 24|2@1+ (1,0) [0|3] ""  IMM
 SG_ M2I_Byrack_ReVeEnable_IMM22_18 : 26|2@1+ (1,0) [0|3] ""  IMM
 SG_ Reserved_18 : 28|4@1+ (1,0) [0|15] ""  IMM
 SG_ M2I_Byrack_IsPostTm_IMM22_18 : 32|8@1+ (0.01,0) [0|2.55] "s"  IMM
 SG_ M2I_Byrack_SysABStTm_IMM22_18 : 40|16@1+ (0.01,0) [0|655.35] "s"  IMM
 SG_ Reserved_18 : 56|8@1+ (1,0) [0|255] ""  IMM

BO_ 2332112547 M2I_Byrack_SUMDATA22__19: 8 MBMU
 SG_ CRC_M2I_Byrack_IMM22_19 : 0|8@1+ (1,0) [0|255] ""  IMM
 SG_ M2I_Byrack_HVS__IMM22_19 : 8|16@1+ (0.1,0) [0|6553.5] "v"  IMM
 SG_ M2I_Byrack_Enable_IMM22_19 : 24|2@1+ (1,0) [0|3] ""  IMM
 SG_ M2I_Byrack_ReVeEnable_IMM22_19 : 26|2@1+ (1,0) [0|3] ""  IMM
 SG_ Reserved_19 : 28|4@1+ (1,0) [0|15] ""  IMM
 SG_ M2I_Byrack_IsPostTm_IMM22_19 : 32|8@1+ (0.01,0) [0|2.55] "s"  IMM
 SG_ M2I_Byrack_SysABStTm_IMM22_19 : 40|16@1+ (0.01,0) [0|655.35] "s"  IMM
 SG_ Reserved_19 : 56|8@1+ (1,0) [0|255] ""  IMM

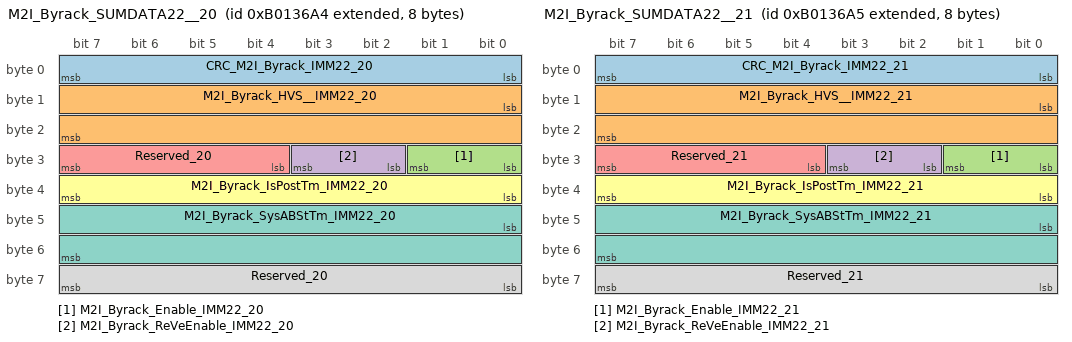
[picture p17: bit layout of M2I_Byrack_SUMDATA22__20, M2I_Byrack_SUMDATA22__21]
BO_ 2332112548 M2I_Byrack_SUMDATA22__20: 8 MBMU
 SG_ CRC_M2I_Byrack_IMM22_20 : 0|8@1+ (1,0) [0|255] ""  IMM
 SG_ M2I_Byrack_HVS__IMM22_20 : 8|16@1+ (0.1,0) [0|6553.5] "v"  IMM
 SG_ M2I_Byrack_Enable_IMM22_20 : 24|2@1+ (1,0) [0|3] ""  IMM
 SG_ M2I_Byrack_ReVeEnable_IMM22_20 : 26|2@1+ (1,0) [0|3] ""  IMM
 SG_ Reserved_20 : 28|4@1+ (1,0) [0|15] ""  IMM
 SG_ M2I_Byrack_IsPostTm_IMM22_20 : 32|8@1+ (0.01,0) [0|2.55] "s"  IMM
 SG_ M2I_Byrack_SysABStTm_IMM22_20 : 40|16@1+ (0.01,0) [0|655.35] "s"  IMM
 SG_ Reserved_20 : 56|8@1+ (1,0) [0|255] ""  IMM

BO_ 2332112549 M2I_Byrack_SUMDATA22__21: 8 MBMU
 SG_ CRC_M2I_Byrack_IMM22_21 : 0|8@1+ (1,0) [0|255] ""  IMM
 SG_ M2I_Byrack_HVS__IMM22_21 : 8|16@1+ (0.1,0) [0|6553.5] "v"  IMM
 SG_ M2I_Byrack_Enable_IMM22_21 : 24|2@1+ (1,0) [0|3] ""  IMM
 SG_ M2I_Byrack_ReVeEnable_IMM22_21 : 26|2@1+ (1,0) [0|3] ""  IMM
 SG_ Reserved_21 : 28|4@1+ (1,0) [0|15] ""  IMM
 SG_ M2I_Byrack_IsPostTm_IMM22_21 : 32|8@1+ (0.01,0) [0|2.55] "s"  IMM
 SG_ M2I_Byrack_SysABStTm_IMM22_21 : 40|16@1+ (0.01,0) [0|655.35] "s"  IMM
 SG_ Reserved_21 : 56|8@1+ (1,0) [0|255] ""  IMM

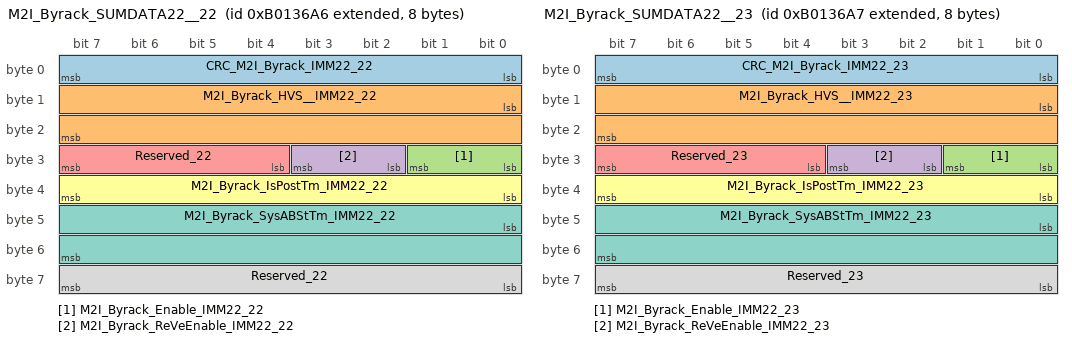
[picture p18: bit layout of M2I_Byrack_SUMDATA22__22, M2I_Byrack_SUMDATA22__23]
BO_ 2332112550 M2I_Byrack_SUMDATA22__22: 8 MBMU
 SG_ CRC_M2I_Byrack_IMM22_22 : 0|8@1+ (1,0) [0|255] ""  IMM
 SG_ M2I_Byrack_HVS__IMM22_22 : 8|16@1+ (0.1,0) [0|6553.5] "v"  IMM
 SG_ M2I_Byrack_Enable_IMM22_22 : 24|2@1+ (1,0) [0|3] ""  IMM
 SG_ M2I_Byrack_ReVeEnable_IMM22_22 : 26|2@1+ (1,0) [0|3] ""  IMM
 SG_ Reserved_22 : 28|4@1+ (1,0) [0|15] ""  IMM
 SG_ M2I_Byrack_IsPostTm_IMM22_22 : 32|8@1+ (0.01,0) [0|2.55] "s"  IMM
 SG_ M2I_Byrack_SysABStTm_IMM22_22 : 40|16@1+ (0.01,0) [0|655.35] "s"  IMM
 SG_ Reserved_22 : 56|8@1+ (1,0) [0|255] ""  IMM

BO_ 2332112551 M2I_Byrack_SUMDATA22__23: 8 MBMU
 SG_ CRC_M2I_Byrack_IMM22_23 : 0|8@1+ (1,0) [0|255] ""  IMM
 SG_ M2I_Byrack_HVS__IMM22_23 : 8|16@1+ (0.1,0) [0|6553.5] "v"  IMM
 SG_ M2I_Byrack_Enable_IMM22_23 : 24|2@1+ (1,0) [0|3] ""  IMM
 SG_ M2I_Byrack_ReVeEnable_IMM22_23 : 26|2@1+ (1,0) [0|3] ""  IMM
 SG_ Reserved_23 : 28|4@1+ (1,0) [0|15] ""  IMM
 SG_ M2I_Byrack_IsPostTm_IMM22_23 : 32|8@1+ (0.01,0) [0|2.55] "s"  IMM
 SG_ M2I_Byrack_SysABStTm_IMM22_23 : 40|16@1+ (0.01,0) [0|655.35] "s"  IMM
 SG_ Reserved_23 : 56|8@1+ (1,0) [0|255] ""  IMM

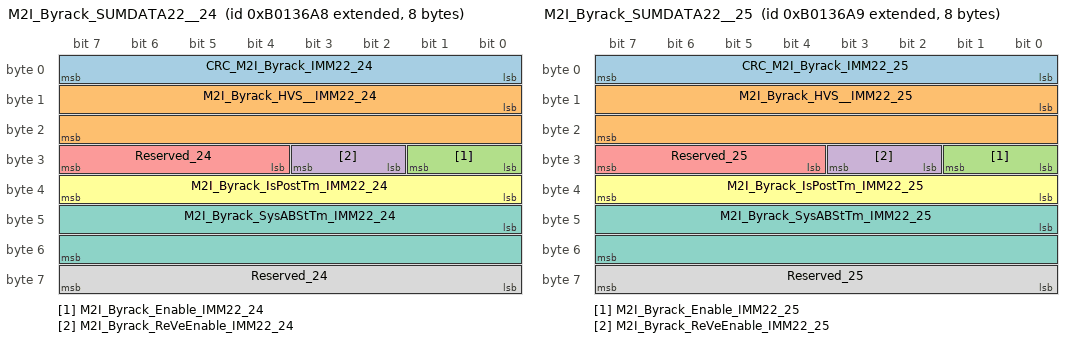
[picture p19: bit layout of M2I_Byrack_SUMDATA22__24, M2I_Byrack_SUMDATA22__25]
BO_ 2332112552 M2I_Byrack_SUMDATA22__24: 8 MBMU
 SG_ CRC_M2I_Byrack_IMM22_24 : 0|8@1+ (1,0) [0|255] ""  IMM
 SG_ M2I_Byrack_HVS__IMM22_24 : 8|16@1+ (0.1,0) [0|6553.5] "v"  IMM
 SG_ M2I_Byrack_Enable_IMM22_24 : 24|2@1+ (1,0) [0|3] ""  IMM
 SG_ M2I_Byrack_ReVeEnable_IMM22_24 : 26|2@1+ (1,0) [0|3] ""  IMM
 SG_ Reserved_24 : 28|4@1+ (1,0) [0|15] ""  IMM
 SG_ M2I_Byrack_IsPostTm_IMM22_24 : 32|8@1+ (0.01,0) [0|2.55] "s"  IMM
 SG_ M2I_Byrack_SysABStTm_IMM22_24 : 40|16@1+ (0.01,0) [0|655.35] "s"  IMM
 SG_ Reserved_24 : 56|8@1+ (1,0) [0|255] ""  IMM

BO_ 2332112553 M2I_Byrack_SUMDATA22__25: 8 MBMU
 SG_ CRC_M2I_Byrack_IMM22_25 : 0|8@1+ (1,0) [0|255] ""  IMM
 SG_ M2I_Byrack_HVS__IMM22_25 : 8|16@1+ (0.1,0) [0|6553.5] "v"  IMM
 SG_ M2I_Byrack_Enable_IMM22_25 : 24|2@1+ (1,0) [0|3] ""  IMM
 SG_ M2I_Byrack_ReVeEnable_IMM22_25 : 26|2@1+ (1,0) [0|3] ""  IMM
 SG_ Reserved_25 : 28|4@1+ (1,0) [0|15] ""  IMM
 SG_ M2I_Byrack_IsPostTm_IMM22_25 : 32|8@1+ (0.01,0) [0|2.55] "s"  IMM
 SG_ M2I_Byrack_SysABStTm_IMM22_25 : 40|16@1+ (0.01,0) [0|655.35] "s"  IMM
 SG_ Reserved_25 : 56|8@1+ (1,0) [0|255] ""  IMM

BO_ 2332112554 M2I_Byrack_SUMDATA22__26: 8 MBMU
 SG_ CRC_M2I_Byrack_IMM22_26 : 0|8@1+ (1,0) [0|255] ""  IMM
 SG_ M2I_Byrack_HVS__IMM22_26 : 8|16@1+ (0.1,0) [0|6553.5] "v"  IMM
 SG_ M2I_Byrack_Enable_IMM22_26 : 24|2@1+ (1,0) [0|3] ""  IMM
 SG_ M2I_Byrack_ReVeEnable_IMM22_26 : 26|2@1+ (1,0) [0|3] ""  IMM
 SG_ Reserved_26 : 28|4@1+ (1,0) [0|15] ""  IMM
 SG_ M2I_Byrack_IsPostTm_IMM22_26 : 32|8@1+ (0.01,0) [0|2.55] "s"  IMM
 SG_ M2I_Byrack_SysABStTm_IMM22_26 : 40|16@1+ (0.01,0) [0|655.35] "s"  IMM
 SG_ Reserved_26 : 56|8@1+ (1,0) [0|255] ""  IMM

BO_ 2332112555 M2I_Byrack_SUMDATA22__27: 8 MBMU
 SG_ CRC_M2I_Byrack_IMM22_27 : 0|8@1+ (1,0) [0|255] ""  IMM
 SG_ M2I_Byrack_HVS__IMM22_27 : 8|16@1+ (0.1,0) [0|6553.5] "v"  IMM
 SG_ M2I_Byrack_Enable_IMM22_27 : 24|2@1+ (1,0) [0|3] ""  IMM
 SG_ M2I_Byrack_ReVeEnable_IMM22_27 : 26|2@1+ (1,0) [0|3] ""  IMM
 SG_ Reserved_27 : 28|4@1+ (1,0) [0|15] ""  IMM
 SG_ M2I_Byrack_IsPostTm_IMM22_27 : 32|8@1+ (0.01,0) [0|2.55] "s"  IMM
 SG_ M2I_Byrack_SysABStTm_IMM22_27 : 40|16@1+ (0.01,0) [0|655.35] "s"  IMM
 SG_ Reserved_27 : 56|8@1+ (1,0) [0|255] ""  IMM

BO_ 2332112556 M2I_Byrack_SUMDATA22__28: 8 MBMU
 SG_ CRC_M2I_Byrack_IMM22_28 : 0|8@1+ (1,0) [0|255] ""  IMM
 SG_ M2I_Byrack_HVS__IMM22_28 : 8|16@1+ (0.1,0) [0|6553.5] "v"  IMM
 SG_ M2I_Byrack_Enable_IMM22_28 : 24|2@1+ (1,0) [0|3] ""  IMM
 SG_ M2I_Byrack_ReVeEnable_IMM22_28 : 26|2@1+ (1,0) [0|3] ""  IMM
 SG_ Reserved_28 : 28|4@1+ (1,0) [0|15] ""  IMM
 SG_ M2I_Byrack_IsPostTm_IMM22_28 : 32|8@1+ (0.01,0) [0|2.55] "s"  IMM
 SG_ M2I_Byrack_SysABStTm_IMM22_28 : 40|16@1+ (0.01,0) [0|655.35] "s"  IMM
 SG_ Reserved_28 : 56|8@1+ (1,0) [0|255] ""  IMM

BO_ 2332112557 M2I_Byrack_SUMDATA22__29: 8 MBMU
 SG_ CRC_M2I_Byrack_IMM22_29 : 0|8@1+ (1,0) [0|255] ""  IMM
 SG_ M2I_Byrack_HVS__IMM22_29 : 8|16@1+ (0.1,0) [0|6553.5] "v"  IMM
 SG_ M2I_Byrack_Enable_IMM22_29 : 24|2@1+ (1,0) [0|3] ""  IMM
 SG_ M2I_Byrack_ReVeEnable_IMM22_29 : 26|2@1+ (1,0) [0|3] ""  IMM
 SG_ Reserved_29 : 28|4@1+ (1,0) [0|15] ""  IMM
 SG_ M2I_Byrack_IsPostTm_IMM22_29 : 32|8@1+ (0.01,0) [0|2.55] "s"  IMM
 SG_ M2I_Byrack_SysABStTm_IMM22_29 : 40|16@1+ (0.01,0) [0|655.35] "s"  IMM
 SG_ Reserved_29 : 56|8@1+ (1,0) [0|255] ""  IMM

BO_ 2332112558 M2I_Byrack_SUMDATA22__30: 8 MBMU
 SG_ CRC_M2I_Byrack_IMM22_30 : 0|8@1+ (1,0) [0|255] ""  IMM
 SG_ M2I_Byrack_HVS__IMM22_30 : 8|16@1+ (0.1,0) [0|6553.5] "v"  IMM
 SG_ M2I_Byrack_Enable_IMM22_30 : 24|2@1+ (1,0) [0|3] ""  IMM
 SG_ M2I_Byrack_ReVeEnable_IMM22_30 : 26|2@1+ (1,0) [0|3] ""  IMM
 SG_ Reserved_30 : 28|4@1+ (1,0) [0|15] ""  IMM
 SG_ M2I_Byrack_IsPostTm_IMM22_30 : 32|8@1+ (0.01,0) [0|2.55] "s"  IMM
 SG_ M2I_Byrack_SysABStTm_IMM22_30 : 40|16@1+ (0.01,0) [0|655.35] "s"  IMM
 SG_ Reserved_30 : 56|8@1+ (1,0) [0|255] ""  IMM

BO_ 2332112559 M2I_Byrack_SUMDATA22__31: 8 MBMU
 SG_ CRC_M2I_Byrack_IMM22_31 : 0|8@1+ (1,0) [0|255] ""  IMM
 SG_ M2I_Byrack_HVS__IMM22_31 : 8|16@1+ (0.1,0) [0|6553.5] "v"  IMM
 SG_ M2I_Byrack_Enable_IMM22_31 : 24|2@1+ (1,0) [0|3] ""  IMM
 SG_ M2I_Byrack_ReVeEnable_IMM22_31 : 26|2@1+ (1,0) [0|3] ""  IMM
 SG_ Reserved_31 : 28|4@1+ (1,0) [0|15] ""  IMM
 SG_ M2I_Byrack_IsPostTm_IMM22_31 : 32|8@1+ (0.01,0) [0|2.55] "s"  IMM
 SG_ M2I_Byrack_SysABStTm_IMM22_31 : 40|16@1+ (0.01,0) [0|655.35] "s"  IMM
 SG_ Reserved_31 : 56|8@1+ (1,0) [0|255] ""  IMM

BO_ 2332112785 M2I_Byrack_SUMDATA23__01: 8 MBMU
 SG_ CRC_M2I_Byrack_IMM23_01 : 0|8@1+ (1,0) [0|255] ""  IMM
 SG_ M2I_Byrack_HVS__IMM23_01 : 8|16@1+ (0.1,0) [0|6553.5] "v"  IMM
 SG_ M2I_Byrack_Enable_IMM23_01 : 24|2@1+ (1,0) [0|3] ""  IMM
 SG_ M2I_Byrack_ReVeEnable_IMM23_01 : 26|2@1+ (1,0) [0|3] ""  IMM
 SG_ Reserved_01 : 28|4@1+ (1,0) [0|15] ""  IMM
 SG_ M2I_Byrack_IsPostTm_IMM23_01 : 32|8@1+ (0.01,0) [0|2.55] "s"  IMM
 SG_ M2I_Byrack_SysABStTm_IMM23_01 : 40|16@1+ (0.01,0) [0|655.35] "s"  IMM
 SG_ Reserved_01 : 56|8@1+ (1,0) [0|255] ""  IMM

BO_ 2332112786 M2I_Byrack_SUMDATA23__02: 8 MBMU
 SG_ CRC_M2I_Byrack_IMM23_02 : 0|8@1+ (1,0) [0|255] ""  IMM
 SG_ M2I_Byrack_HVS__IMM23_02 : 8|16@1+ (0.1,0) [0|6553.5] "v"  IMM
 SG_ M2I_Byrack_Enable_IMM23_02 : 24|2@1+ (1,0) [0|3] ""  IMM
 SG_ M2I_Byrack_ReVeEnable_IMM23_02 : 26|2@1+ (1,0) [0|3] ""  IMM
 SG_ Reserved_02 : 28|4@1+ (1,0) [0|15] ""  IMM
 SG_ M2I_Byrack_IsPostTm_IMM23_02 : 32|8@1+ (0.01,0) [0|2.55] "s"  IMM
 SG_ M2I_Byrack_SysABStTm_IMM23_02 : 40|16@1+ (0.01,0) [0|655.35] "s"  IMM
 SG_ Reserved_02 : 56|8@1+ (1,0) [0|255] ""  IMM

BO_ 2332112787 M2I_Byrack_SUMDATA23__03: 8 MBMU
 SG_ CRC_M2I_Byrack_IMM23_03 : 0|8@1+ (1,0) [0|255] ""  IMM
 SG_ M2I_Byrack_HVS__IMM23_03 : 8|16@1+ (0.1,0) [0|6553.5] "v"  IMM
 SG_ M2I_Byrack_Enable_IMM23_03 : 24|2@1+ (1,0) [0|3] ""  IMM
 SG_ M2I_Byrack_ReVeEnable_IMM23_03 : 26|2@1+ (1,0) [0|3] ""  IMM
 SG_ Reserved_03 : 28|4@1+ (1,0) [0|15] ""  IMM
 SG_ M2I_Byrack_IsPostTm_IMM23_03 : 32|8@1+ (0.01,0) [0|2.55] "s"  IMM
 SG_ M2I_Byrack_SysABStTm_IMM23_03 : 40|16@1+ (0.01,0) [0|655.35] "s"  IMM
 SG_ Reserved_03 : 56|8@1+ (1,0) [0|255] ""  IMM

BO_ 2332112788 M2I_Byrack_SUMDATA23__04: 8 MBMU
 SG_ CRC_M2I_Byrack_IMM23_04 : 0|8@1+ (1,0) [0|255] ""  IMM
 SG_ M2I_Byrack_HVS__IMM23_04 : 8|16@1+ (0.1,0) [0|6553.5] "v"  IMM
 SG_ M2I_Byrack_Enable_IMM23_04 : 24|2@1+ (1,0) [0|3] ""  IMM
 SG_ M2I_Byrack_ReVeEnable_IMM23_04 : 26|2@1+ (1,0) [0|3] ""  IMM
 SG_ Reserved_04 : 28|4@1+ (1,0) [0|15] ""  IMM
 SG_ M2I_Byrack_IsPostTm_IMM23_04 : 32|8@1+ (0.01,0) [0|2.55] "s"  IMM
 SG_ M2I_Byrack_SysABStTm_IMM23_04 : 40|16@1+ (0.01,0) [0|655.35] "s"  IMM
 SG_ Reserved_04 : 56|8@1+ (1,0) [0|255] ""  IMM

BO_ 2332112789 M2I_Byrack_SUMDATA23__05: 8 MBMU
 SG_ CRC_M2I_Byrack_IMM23_05 : 0|8@1+ (1,0) [0|255] ""  IMM
 SG_ M2I_Byrack_HVS__IMM23_05 : 8|16@1+ (0.1,0) [0|6553.5] "v"  IMM
 SG_ M2I_Byrack_Enable_IMM23_05 : 24|2@1+ (1,0) [0|3] ""  IMM
 SG_ M2I_Byrack_ReVeEnable_IMM23_05 : 26|2@1+ (1,0) [0|3] ""  IMM
 SG_ Reserved_05 : 28|4@1+ (1,0) [0|15] ""  IMM
 SG_ M2I_Byrack_IsPostTm_IMM23_05 : 32|8@1+ (0.01,0) [0|2.55] "s"  IMM
 SG_ M2I_Byrack_SysABStTm_IMM23_05 : 40|16@1+ (0.01,0) [0|655.35] "s"  IMM
 SG_ Reserved_05 : 56|8@1+ (1,0) [0|255] ""  IMM

BO_ 2332112790 M2I_Byrack_SUMDATA23__06: 8 MBMU
 SG_ CRC_M2I_Byrack_IMM23_06 : 0|8@1+ (1,0) [0|255] ""  IMM
 SG_ M2I_Byrack_HVS__IMM23_06 : 8|16@1+ (0.1,0) [0|6553.5] "v"  IMM
 SG_ M2I_Byrack_Enable_IMM23_06 : 24|2@1+ (1,0) [0|3] ""  IMM
 SG_ M2I_Byrack_ReVeEnable_IMM23_06 : 26|2@1+ (1,0) [0|3] ""  IMM
 SG_ Reserved_06 : 28|4@1+ (1,0) [0|15] ""  IMM
 SG_ M2I_Byrack_IsPostTm_IMM23_06 : 32|8@1+ (0.01,0) [0|2.55] "s"  IMM
 SG_ M2I_Byrack_SysABStTm_IMM23_06 : 40|16@1+ (0.01,0) [0|655.35] "s"  IMM
 SG_ Reserved_06 : 56|8@1+ (1,0) [0|255] ""  IMM

BO_ 2332112791 M2I_Byrack_SUMDATA23__07: 8 MBMU
 SG_ CRC_M2I_Byrack_IMM23_07 : 0|8@1+ (1,0) [0|255] ""  IMM
 SG_ M2I_Byrack_HVS__IMM23_07 : 8|16@1+ (0.1,0) [0|6553.5] "v"  IMM
 SG_ M2I_Byrack_Enable_IMM23_07 : 24|2@1+ (1,0) [0|3] ""  IMM
 SG_ M2I_Byrack_ReVeEnable_IMM23_07 : 26|2@1+ (1,0) [0|3] ""  IMM
 SG_ Reserved_07 : 28|4@1+ (1,0) [0|15] ""  IMM
 SG_ M2I_Byrack_IsPostTm_IMM23_07 : 32|8@1+ (0.01,0) [0|2.55] "s"  IMM
 SG_ M2I_Byrack_SysABStTm_IMM23_07 : 40|16@1+ (0.01,0) [0|655.35] "s"  IMM
 SG_ Reserved_07 : 56|8@1+ (1,0) [0|255] ""  IMM

BO_ 2332112792 M2I_Byrack_SUMDATA23__08: 8 MBMU
 SG_ CRC_M2I_Byrack_IMM23_08 : 0|8@1+ (1,0) [0|255] ""  IMM
 SG_ M2I_Byrack_HVS__IMM23_08 : 8|16@1+ (0.1,0) [0|6553.5] "v"  IMM
 SG_ M2I_Byrack_Enable_IMM23_08 : 24|2@1+ (1,0) [0|3] ""  IMM
 SG_ M2I_Byrack_ReVeEnable_IMM23_08 : 26|2@1+ (1,0) [0|3] ""  IMM
 SG_ Reserved_08 : 28|4@1+ (1,0) [0|15] ""  IMM
 SG_ M2I_Byrack_IsPostTm_IMM23_08 : 32|8@1+ (0.01,0) [0|2.55] "s"  IMM
 SG_ M2I_Byrack_SysABStTm_IMM23_08 : 40|16@1+ (0.01,0) [0|655.35] "s"  IMM
 SG_ Reserved_08 : 56|8@1+ (1,0) [0|255] ""  IMM

BO_ 2332112793 M2I_Byrack_SUMDATA23__09: 8 MBMU
 SG_ CRC_M2I_Byrack_IMM23_09 : 0|8@1+ (1,0) [0|255] ""  IMM
 SG_ M2I_Byrack_HVS__IMM23_09 : 8|16@1+ (0.1,0) [0|6553.5] "v"  IMM
 SG_ M2I_Byrack_Enable_IMM23_09 : 24|2@1+ (1,0) [0|3] ""  IMM
 SG_ M2I_Byrack_ReVeEnable_IMM23_09 : 26|2@1+ (1,0) [0|3] ""  IMM
 SG_ Reserved_09 : 28|4@1+ (1,0) [0|15] ""  IMM
 SG_ M2I_Byrack_IsPostTm_IMM23_09 : 32|8@1+ (0.01,0) [0|2.55] "s"  IMM
 SG_ M2I_Byrack_SysABStTm_IMM23_09 : 40|16@1+ (0.01,0) [0|655.35] "s"  IMM
 SG_ Reserved_09 : 56|8@1+ (1,0) [0|255] ""  IMM

BO_ 2332112794 M2I_Byrack_SUMDATA23__10: 8 MBMU
 SG_ CRC_M2I_Byrack_IMM23_10 : 0|8@1+ (1,0) [0|255] ""  IMM
 SG_ M2I_Byrack_HVS__IMM23_10 : 8|16@1+ (0.1,0) [0|6553.5] "v"  IMM
 SG_ M2I_Byrack_Enable_IMM23_10 : 24|2@1+ (1,0) [0|3] ""  IMM
 SG_ M2I_Byrack_ReVeEnable_IMM23_10 : 26|2@1+ (1,0) [0|3] ""  IMM
 SG_ Reserved_10 : 28|4@1+ (1,0) [0|15] ""  IMM
 SG_ M2I_Byrack_IsPostTm_IMM23_10 : 32|8@1+ (0.01,0) [0|2.55] "s"  IMM
 SG_ M2I_Byrack_SysABStTm_IMM23_10 : 40|16@1+ (0.01,0) [0|655.35] "s"  IMM
 SG_ Reserved_10 : 56|8@1+ (1,0) [0|255] ""  IMM

BO_ 2332112795 M2I_Byrack_SUMDATA23__11: 8 MBMU
 SG_ CRC_M2I_Byrack_IMM23_11 : 0|8@1+ (1,0) [0|255] ""  IMM
 SG_ M2I_Byrack_HVS__IMM23_11 : 8|16@1+ (0.1,0) [0|6553.5] "v"  IMM
 SG_ M2I_Byrack_Enable_IMM23_11 : 24|2@1+ (1,0) [0|3] ""  IMM
 SG_ M2I_Byrack_ReVeEnable_IMM23_11 : 26|2@1+ (1,0) [0|3] ""  IMM
 SG_ Reserved_11 : 28|4@1+ (1,0) [0|15] ""  IMM
 SG_ M2I_Byrack_IsPostTm_IMM23_11 : 32|8@1+ (0.01,0) [0|2.55] "s"  IMM
 SG_ M2I_Byrack_SysABStTm_IMM23_11 : 40|16@1+ (0.01,0) [0|655.35] "s"  IMM
 SG_ Reserved_11 : 56|8@1+ (1,0) [0|255] ""  IMM

BO_ 2332112796 M2I_Byrack_SUMDATA23__12: 8 MBMU
 SG_ CRC_M2I_Byrack_IMM23_12 : 0|8@1+ (1,0) [0|255] ""  IMM
 SG_ M2I_Byrack_HVS__IMM23_12 : 8|16@1+ (0.1,0) [0|6553.5] "v"  IMM
 SG_ M2I_Byrack_Enable_IMM23_12 : 24|2@1+ (1,0) [0|3] ""  IMM
 SG_ M2I_Byrack_ReVeEnable_IMM23_12 : 26|2@1+ (1,0) [0|3] ""  IMM
 SG_ Reserved_12 : 28|4@1+ (1,0) [0|15] ""  IMM
 SG_ M2I_Byrack_IsPostTm_IMM23_12 : 32|8@1+ (0.01,0) [0|2.55] "s"  IMM
 SG_ M2I_Byrack_SysABStTm_IMM23_12 : 40|16@1+ (0.01,0) [0|655.35] "s"  IMM
 SG_ Reserved_12 : 56|8@1+ (1,0) [0|255] ""  IMM

BO_ 2332112797 M2I_Byrack_SUMDATA23__13: 8 MBMU
 SG_ CRC_M2I_Byrack_IMM23_13 : 0|8@1+ (1,0) [0|255] ""  IMM
 SG_ M2I_Byrack_HVS__IMM23_13 : 8|16@1+ (0.1,0) [0|6553.5] "v"  IMM
 SG_ M2I_Byrack_Enable_IMM23_13 : 24|2@1+ (1,0) [0|3] ""  IMM
 SG_ M2I_Byrack_ReVeEnable_IMM23_13 : 26|2@1+ (1,0) [0|3] ""  IMM
 SG_ Reserved_13 : 28|4@1+ (1,0) [0|15] ""  IMM
 SG_ M2I_Byrack_IsPostTm_IMM23_13 : 32|8@1+ (0.01,0) [0|2.55] "s"  IMM
 SG_ M2I_Byrack_SysABStTm_IMM23_13 : 40|16@1+ (0.01,0) [0|655.35] "s"  IMM
 SG_ Reserved_13 : 56|8@1+ (1,0) [0|255] ""  IMM

BO_ 2332112798 M2I_Byrack_SUMDATA23__14: 8 MBMU
 SG_ CRC_M2I_Byrack_IMM23_14 : 0|8@1+ (1,0) [0|255] ""  IMM
 SG_ M2I_Byrack_HVS__IMM23_14 : 8|16@1+ (0.1,0) [0|6553.5] "v"  IMM
 SG_ M2I_Byrack_Enable_IMM23_14 : 24|2@1+ (1,0) [0|3] ""  IMM
 SG_ M2I_Byrack_ReVeEnable_IMM23_14 : 26|2@1+ (1,0) [0|3] ""  IMM
 SG_ Reserved_14 : 28|4@1+ (1,0) [0|15] ""  IMM
 SG_ M2I_Byrack_IsPostTm_IMM23_14 : 32|8@1+ (0.01,0) [0|2.55] "s"  IMM
 SG_ M2I_Byrack_SysABStTm_IMM23_14 : 40|16@1+ (0.01,0) [0|655.35] "s"  IMM
 SG_ Reserved_14 : 56|8@1+ (1,0) [0|255] ""  IMM

BO_ 2332112799 M2I_Byrack_SUMDATA23__15: 8 MBMU
 SG_ CRC_M2I_Byrack_IMM23_15 : 0|8@1+ (1,0) [0|255] ""  IMM
 SG_ M2I_Byrack_HVS__IMM23_15 : 8|16@1+ (0.1,0) [0|6553.5] "v"  IMM
 SG_ M2I_Byrack_Enable_IMM23_15 : 24|2@1+ (1,0) [0|3] ""  IMM
 SG_ M2I_Byrack_ReVeEnable_IMM23_15 : 26|2@1+ (1,0) [0|3] ""  IMM
 SG_ Reserved_15 : 28|4@1+ (1,0) [0|15] ""  IMM
 SG_ M2I_Byrack_IsPostTm_IMM23_15 : 32|8@1+ (0.01,0) [0|2.55] "s"  IMM
 SG_ M2I_Byrack_SysABStTm_IMM23_15 : 40|16@1+ (0.01,0) [0|655.35] "s"  IMM
 SG_ Reserved_15 : 56|8@1+ (1,0) [0|255] ""  IMM

BO_ 2332112800 M2I_Byrack_SUMDATA23__16: 8 MBMU
 SG_ CRC_M2I_Byrack_IMM23_16 : 0|8@1+ (1,0) [0|255] ""  IMM
 SG_ M2I_Byrack_HVS__IMM23_16 : 8|16@1+ (0.1,0) [0|6553.5] "v"  IMM
 SG_ M2I_Byrack_Enable_IMM23_16 : 24|2@1+ (1,0) [0|3] ""  IMM
 SG_ M2I_Byrack_ReVeEnable_IMM23_16 : 26|2@1+ (1,0) [0|3] ""  IMM
 SG_ Reserved_16 : 28|4@1+ (1,0) [0|15] ""  IMM
 SG_ M2I_Byrack_IsPostTm_IMM23_16 : 32|8@1+ (0.01,0) [0|2.55] "s"  IMM
 SG_ M2I_Byrack_SysABStTm_IMM23_16 : 40|16@1+ (0.01,0) [0|655.35] "s"  IMM
 SG_ Reserved_16 : 56|8@1+ (1,0) [0|255] ""  IMM

BO_ 2332112801 M2I_Byrack_SUMDATA23__17: 8 MBMU
 SG_ CRC_M2I_Byrack_IMM23_17 : 0|8@1+ (1,0) [0|255] ""  IMM
 SG_ M2I_Byrack_HVS__IMM23_17 : 8|16@1+ (0.1,0) [0|6553.5] "v"  IMM
 SG_ M2I_Byrack_Enable_IMM23_17 : 24|2@1+ (1,0) [0|3] ""  IMM
 SG_ M2I_Byrack_ReVeEnable_IMM23_17 : 26|2@1+ (1,0) [0|3] ""  IMM
 SG_ Reserved_17 : 28|4@1+ (1,0) [0|15] ""  IMM
 SG_ M2I_Byrack_IsPostTm_IMM23_17 : 32|8@1+ (0.01,0) [0|2.55] "s"  IMM
 SG_ M2I_Byrack_SysABStTm_IMM23_17 : 40|16@1+ (0.01,0) [0|655.35] "s"  IMM
 SG_ Reserved_17 : 56|8@1+ (1,0) [0|255] ""  IMM

BO_ 2332112802 M2I_Byrack_SUMDATA23__18: 8 MBMU
 SG_ CRC_M2I_Byrack_IMM23_18 : 0|8@1+ (1,0) [0|255] ""  IMM
 SG_ M2I_Byrack_HVS__IMM23_18 : 8|16@1+ (0.1,0) [0|6553.5] "v"  IMM
 SG_ M2I_Byrack_Enable_IMM23_18 : 24|2@1+ (1,0) [0|3] ""  IMM
 SG_ M2I_Byrack_ReVeEnable_IMM23_18 : 26|2@1+ (1,0) [0|3] ""  IMM
 SG_ Reserved_18 : 28|4@1+ (1,0) [0|15] ""  IMM
 SG_ M2I_Byrack_IsPostTm_IMM23_18 : 32|8@1+ (0.01,0) [0|2.55] "s"  IMM
 SG_ M2I_Byrack_SysABStTm_IMM23_18 : 40|16@1+ (0.01,0) [0|655.35] "s"  IMM
 SG_ Reserved_18 : 56|8@1+ (1,0) [0|255] ""  IMM

BO_ 2332112803 M2I_Byrack_SUMDATA23__19: 8 MBMU
 SG_ CRC_M2I_Byrack_IMM23_19 : 0|8@1+ (1,0) [0|255] ""  IMM
 SG_ M2I_Byrack_HVS__IMM23_19 : 8|16@1+ (0.1,0) [0|6553.5] "v"  IMM
 SG_ M2I_Byrack_Enable_IMM23_19 : 24|2@1+ (1,0) [0|3] ""  IMM
 SG_ M2I_Byrack_ReVeEnable_IMM23_19 : 26|2@1+ (1,0) [0|3] ""  IMM
 SG_ Reserved_19 : 28|4@1+ (1,0) [0|15] ""  IMM
 SG_ M2I_Byrack_IsPostTm_IMM23_19 : 32|8@1+ (0.01,0) [0|2.55] "s"  IMM
 SG_ M2I_Byrack_SysABStTm_IMM23_19 : 40|16@1+ (0.01,0) [0|655.35] "s"  IMM
 SG_ Reserved_19 : 56|8@1+ (1,0) [0|255] ""  IMM

BO_ 2332112804 M2I_Byrack_SUMDATA23__20: 8 MBMU
 SG_ CRC_M2I_Byrack_IMM23_20 : 0|8@1+ (1,0) [0|255] ""  IMM
 SG_ M2I_Byrack_HVS__IMM23_20 : 8|16@1+ (0.1,0) [0|6553.5] "v"  IMM
 SG_ M2I_Byrack_Enable_IMM23_20 : 24|2@1+ (1,0) [0|3] ""  IMM
 SG_ M2I_Byrack_ReVeEnable_IMM23_20 : 26|2@1+ (1,0) [0|3] ""  IMM
 SG_ Reserved_20 : 28|4@1+ (1,0) [0|15] ""  IMM
 SG_ M2I_Byrack_IsPostTm_IMM23_20 : 32|8@1+ (0.01,0) [0|2.55] "s"  IMM
 SG_ M2I_Byrack_SysABStTm_IMM23_20 : 40|16@1+ (0.01,0) [0|655.35] "s"  IMM
 SG_ Reserved_20 : 56|8@1+ (1,0) [0|255] ""  IMM

BO_ 2332112805 M2I_Byrack_SUMDATA23__21: 8 MBMU
 SG_ CRC_M2I_Byrack_IMM23_21 : 0|8@1+ (1,0) [0|255] ""  IMM
 SG_ M2I_Byrack_HVS__IMM23_21 : 8|16@1+ (0.1,0) [0|6553.5] "v"  IMM
 SG_ M2I_Byrack_Enable_IMM23_21 : 24|2@1+ (1,0) [0|3] ""  IMM
 SG_ M2I_Byrack_ReVeEnable_IMM23_21 : 26|2@1+ (1,0) [0|3] ""  IMM
 SG_ Reserved_21 : 28|4@1+ (1,0) [0|15] ""  IMM
 SG_ M2I_Byrack_IsPostTm_IMM23_21 : 32|8@1+ (0.01,0) [0|2.55] "s"  IMM
 SG_ M2I_Byrack_SysABStTm_IMM23_21 : 40|16@1+ (0.01,0) [0|655.35] "s"  IMM
 SG_ Reserved_21 : 56|8@1+ (1,0) [0|255] ""  IMM

BO_ 2332112806 M2I_Byrack_SUMDATA23__22: 8 MBMU
 SG_ CRC_M2I_Byrack_IMM23_22 : 0|8@1+ (1,0) [0|255] ""  IMM
 SG_ M2I_Byrack_HVS__IMM23_22 : 8|16@1+ (0.1,0) [0|6553.5] "v"  IMM
 SG_ M2I_Byrack_Enable_IMM23_22 : 24|2@1+ (1,0) [0|3] ""  IMM
 SG_ M2I_Byrack_ReVeEnable_IMM23_22 : 26|2@1+ (1,0) [0|3] ""  IMM
 SG_ Reserved_22 : 28|4@1+ (1,0) [0|15] ""  IMM
 SG_ M2I_Byrack_IsPostTm_IMM23_22 : 32|8@1+ (0.01,0) [0|2.55] "s"  IMM
 SG_ M2I_Byrack_SysABStTm_IMM23_22 : 40|16@1+ (0.01,0) [0|655.35] "s"  IMM
 SG_ Reserved_22 : 56|8@1+ (1,0) [0|255] ""  IMM

BO_ 2332112807 M2I_Byrack_SUMDATA23__23: 8 MBMU
 SG_ CRC_M2I_Byrack_IMM23_23 : 0|8@1+ (1,0) [0|255] ""  IMM
 SG_ M2I_Byrack_HVS__IMM23_23 : 8|16@1+ (0.1,0) [0|6553.5] "v"  IMM
 SG_ M2I_Byrack_Enable_IMM23_23 : 24|2@1+ (1,0) [0|3] ""  IMM
 SG_ M2I_Byrack_ReVeEnable_IMM23_23 : 26|2@1+ (1,0) [0|3] ""  IMM
 SG_ Reserved_23 : 28|4@1+ (1,0) [0|15] ""  IMM
 SG_ M2I_Byrack_IsPostTm_IMM23_23 : 32|8@1+ (0.01,0) [0|2.55] "s"  IMM
 SG_ M2I_Byrack_SysABStTm_IMM23_23 : 40|16@1+ (0.01,0) [0|655.35] "s"  IMM
 SG_ Reserved_23 : 56|8@1+ (1,0) [0|255] ""  IMM

BO_ 2332112808 M2I_Byrack_SUMDATA23__24: 8 MBMU
 SG_ CRC_M2I_Byrack_IMM23_24 : 0|8@1+ (1,0) [0|255] ""  IMM
 SG_ M2I_Byrack_HVS__IMM23_24 : 8|16@1+ (0.1,0) [0|6553.5] "v"  IMM
 SG_ M2I_Byrack_Enable_IMM23_24 : 24|2@1+ (1,0) [0|3] ""  IMM
 SG_ M2I_Byrack_ReVeEnable_IMM23_24 : 26|2@1+ (1,0) [0|3] ""  IMM
 SG_ Reserved_24 : 28|4@1+ (1,0) [0|15] ""  IMM
 SG_ M2I_Byrack_IsPostTm_IMM23_24 : 32|8@1+ (0.01,0) [0|2.55] "s"  IMM
 SG_ M2I_Byrack_SysABStTm_IMM23_24 : 40|16@1+ (0.01,0) [0|655.35] "s"  IMM
 SG_ Reserved_24 : 56|8@1+ (1,0) [0|255] ""  IMM

BO_ 2332112809 M2I_Byrack_SUMDATA23__25: 8 MBMU
 SG_ CRC_M2I_Byrack_IMM23_25 : 0|8@1+ (1,0) [0|255] ""  IMM
 SG_ M2I_Byrack_HVS__IMM23_25 : 8|16@1+ (0.1,0) [0|6553.5] "v"  IMM
 SG_ M2I_Byrack_Enable_IMM23_25 : 24|2@1+ (1,0) [0|3] ""  IMM
 SG_ M2I_Byrack_ReVeEnable_IMM23_25 : 26|2@1+ (1,0) [0|3] ""  IMM
 SG_ Reserved_25 : 28|4@1+ (1,0) [0|15] ""  IMM
 SG_ M2I_Byrack_IsPostTm_IMM23_25 : 32|8@1+ (0.01,0) [0|2.55] "s"  IMM
 SG_ M2I_Byrack_SysABStTm_IMM23_25 : 40|16@1+ (0.01,0) [0|655.35] "s"  IMM
 SG_ Reserved_25 : 56|8@1+ (1,0) [0|255] ""  IMM

BO_ 2332112810 M2I_Byrack_SUMDATA23__26: 8 MBMU
 SG_ CRC_M2I_Byrack_IMM23_26 : 0|8@1+ (1,0) [0|255] ""  IMM
 SG_ M2I_Byrack_HVS__IMM23_26 : 8|16@1+ (0.1,0) [0|6553.5] "v"  IMM
 SG_ M2I_Byrack_Enable_IMM23_26 : 24|2@1+ (1,0) [0|3] ""  IMM
 SG_ M2I_Byrack_ReVeEnable_IMM23_26 : 26|2@1+ (1,0) [0|3] ""  IMM
 SG_ Reserved_26 : 28|4@1+ (1,0) [0|15] ""  IMM
 SG_ M2I_Byrack_IsPostTm_IMM23_26 : 32|8@1+ (0.01,0) [0|2.55] "s"  IMM
 SG_ M2I_Byrack_SysABStTm_IMM23_26 : 40|16@1+ (0.01,0) [0|655.35] "s"  IMM
 SG_ Reserved_26 : 56|8@1+ (1,0) [0|255] ""  IMM

BO_ 2332112811 M2I_Byrack_SUMDATA23__27: 8 MBMU
 SG_ CRC_M2I_Byrack_IMM23_27 : 0|8@1+ (1,0) [0|255] ""  IMM
 SG_ M2I_Byrack_HVS__IMM23_27 : 8|16@1+ (0.1,0) [0|6553.5] "v"  IMM
 SG_ M2I_Byrack_Enable_IMM23_27 : 24|2@1+ (1,0) [0|3] ""  IMM
 SG_ M2I_Byrack_ReVeEnable_IMM23_27 : 26|2@1+ (1,0) [0|3] ""  IMM
 SG_ Reserved_27 : 28|4@1+ (1,0) [0|15] ""  IMM
 SG_ M2I_Byrack_IsPostTm_IMM23_27 : 32|8@1+ (0.01,0) [0|2.55] "s"  IMM
 SG_ M2I_Byrack_SysABStTm_IMM23_27 : 40|16@1+ (0.01,0) [0|655.35] "s"  IMM
 SG_ Reserved_27 : 56|8@1+ (1,0) [0|255] ""  IMM

BO_ 2332112812 M2I_Byrack_SUMDATA23__28: 8 MBMU
 SG_ CRC_M2I_Byrack_IMM23_28 : 0|8@1+ (1,0) [0|255] ""  IMM
 SG_ M2I_Byrack_HVS__IMM23_28 : 8|16@1+ (0.1,0) [0|6553.5] "v"  IMM
 SG_ M2I_Byrack_Enable_IMM23_28 : 24|2@1+ (1,0) [0|3] ""  IMM
 SG_ M2I_Byrack_ReVeEnable_IMM23_28 : 26|2@1+ (1,0) [0|3] ""  IMM
 SG_ Reserved_28 : 28|4@1+ (1,0) [0|15] ""  IMM
 SG_ M2I_Byrack_IsPostTm_IMM23_28 : 32|8@1+ (0.01,0) [0|2.55] "s"  IMM
 SG_ M2I_Byrack_SysABStTm_IMM23_28 : 40|16@1+ (0.01,0) [0|655.35] "s"  IMM
 SG_ Reserved_28 : 56|8@1+ (1,0) [0|255] ""  IMM

BO_ 2332112813 M2I_Byrack_SUMDATA23__29: 8 MBMU
 SG_ CRC_M2I_Byrack_IMM23_29 : 0|8@1+ (1,0) [0|255] ""  IMM
 SG_ M2I_Byrack_HVS__IMM23_29 : 8|16@1+ (0.1,0) [0|6553.5] "v"  IMM
 SG_ M2I_Byrack_Enable_IMM23_29 : 24|2@1+ (1,0) [0|3] ""  IMM
 SG_ M2I_Byrack_ReVeEnable_IMM23_29 : 26|2@1+ (1,0) [0|3] ""  IMM
 SG_ Reserved_29 : 28|4@1+ (1,0) [0|15] ""  IMM
 SG_ M2I_Byrack_IsPostTm_IMM23_29 : 32|8@1+ (0.01,0) [0|2.55] "s"  IMM
 SG_ M2I_Byrack_SysABStTm_IMM23_29 : 40|16@1+ (0.01,0) [0|655.35] "s"  IMM
 SG_ Reserved_29 : 56|8@1+ (1,0) [0|255] ""  IMM

BO_ 2332112814 M2I_Byrack_SUMDATA23__30: 8 MBMU
 SG_ CRC_M2I_Byrack_IMM23_30 : 0|8@1+ (1,0) [0|255] ""  IMM
 SG_ M2I_Byrack_HVS__IMM23_30 : 8|16@1+ (0.1,0) [0|6553.5] "v"  IMM
 SG_ M2I_Byrack_Enable_IMM23_30 : 24|2@1+ (1,0) [0|3] ""  IMM
 SG_ M2I_Byrack_ReVeEnable_IMM23_30 : 26|2@1+ (1,0) [0|3] ""  IMM
 SG_ Reserved_30 : 28|4@1+ (1,0) [0|15] ""  IMM
 SG_ M2I_Byrack_IsPostTm_IMM23_30 : 32|8@1+ (0.01,0) [0|2.55] "s"  IMM
 SG_ M2I_Byrack_SysABStTm_IMM23_30 : 40|16@1+ (0.01,0) [0|655.35] "s"  IMM
 SG_ Reserved_30 : 56|8@1+ (1,0) [0|255] ""  IMM

BO_ 2332112815 M2I_Byrack_SUMDATA23__31: 8 MBMU
 SG_ CRC_M2I_Byrack_IMM23_31 : 0|8@1+ (1,0) [0|255] ""  IMM
 SG_ M2I_Byrack_HVS__IMM23_31 : 8|16@1+ (0.1,0) [0|6553.5] "v"  IMM
 SG_ M2I_Byrack_Enable_IMM23_31 : 24|2@1+ (1,0) [0|3] ""  IMM
 SG_ M2I_Byrack_ReVeEnable_IMM23_31 : 26|2@1+ (1,0) [0|3] ""  IMM
 SG_ Reserved_31 : 28|4@1+ (1,0) [0|15] ""  IMM
 SG_ M2I_Byrack_IsPostTm_IMM23_31 : 32|8@1+ (0.01,0) [0|2.55] "s"  IMM
 SG_ M2I_Byrack_SysABStTm_IMM23_31 : 40|16@1+ (0.01,0) [0|655.35] "s"  IMM
 SG_ Reserved_31 : 56|8@1+ (1,0) [0|255] ""  IMM

BO_ 2332113041 M2I_Byrack_SUMDATA24__01: 8 MBMU
 SG_ CRC_M2I_Byrack_IMM24_01 : 0|8@1+ (1,0) [0|255] ""  IMM
 SG_ M2I_Byrack_HVS_IMM24_01 : 8|16@1+ (0.1,0) [0|6553.5] "v"  IMM
 SG_ M2I_Byrack_Enable_IMM24_01 : 24|2@1+ (1,0) [0|3] ""  IMM
 SG_ M2I_Byrack_ReVeEnable_IMM24_01 : 26|2@1+ (1,0) [0|3] ""  IMM
 SG_ Reserved_01 : 28|4@1+ (1,0) [0|15] ""  IMM
 SG_ M2I_Byrack_IsPostTm_IMM24_01 : 32|8@1+ (0.01,0) [0|2.55] "s"  IMM
 SG_ M2I_Byrack_SysABStTm_IMM24_01 : 40|16@1+ (0.01,0) [0|655.35] "s"  IMM
 SG_ Reserved_01 : 56|8@1+ (1,0) [0|255] ""  IMM

BO_ 2332113042 M2I_Byrack_SUMDATA24__02: 8 MBMU
 SG_ CRC_M2I_Byrack_IMM24_02 : 0|8@1+ (1,0) [0|255] ""  IMM
 SG_ M2I_Byrack_HVS_IMM24_02 : 8|16@1+ (0.1,0) [0|6553.5] "v"  IMM
 SG_ M2I_Byrack_Enable_IMM24_02 : 24|2@1+ (1,0) [0|3] ""  IMM
 SG_ M2I_Byrack_ReVeEnable_IMM24_02 : 26|2@1+ (1,0) [0|3] ""  IMM
 SG_ Reserved_02 : 28|4@1+ (1,0) [0|15] ""  IMM
 SG_ M2I_Byrack_IsPostTm_IMM24_02 : 32|8@1+ (0.01,0) [0|2.55] "s"  IMM
 SG_ M2I_Byrack_SysABStTm_IMM24_02 : 40|16@1+ (0.01,0) [0|655.35] "s"  IMM
 SG_ Reserved_02 : 56|8@1+ (1,0) [0|255] ""  IMM

BO_ 2332113043 M2I_Byrack_SUMDATA24__03: 8 MBMU
 SG_ CRC_M2I_Byrack_IMM24_03 : 0|8@1+ (1,0) [0|255] ""  IMM
 SG_ M2I_Byrack_HVS_IMM24_03 : 8|16@1+ (0.1,0) [0|6553.5] "v"  IMM
 SG_ M2I_Byrack_Enable_IMM24_03 : 24|2@1+ (1,0) [0|3] ""  IMM
 SG_ M2I_Byrack_ReVeEnable_IMM24_03 : 26|2@1+ (1,0) [0|3] ""  IMM
 SG_ Reserved_03 : 28|4@1+ (1,0) [0|15] ""  IMM
 SG_ M2I_Byrack_IsPostTm_IMM24_03 : 32|8@1+ (0.01,0) [0|2.55] "s"  IMM
 SG_ M2I_Byrack_SysABStTm_IMM24_03 : 40|16@1+ (0.01,0) [0|655.35] "s"  IMM
 SG_ Reserved_03 : 56|8@1+ (1,0) [0|255] ""  IMM

BO_ 2332113044 M2I_Byrack_SUMDATA24__04: 8 MBMU
 SG_ CRC_M2I_Byrack_IMM24_04 : 0|8@1+ (1,0) [0|255] ""  IMM
 SG_ M2I_Byrack_HVS_IMM24_04 : 8|16@1+ (0.1,0) [0|6553.5] "v"  IMM
 SG_ M2I_Byrack_Enable_IMM24_04 : 24|2@1+ (1,0) [0|3] ""  IMM
 SG_ M2I_Byrack_ReVeEnable_IMM24_04 : 26|2@1+ (1,0) [0|3] ""  IMM
 SG_ Reserved_04 : 28|4@1+ (1,0) [0|15] ""  IMM
 SG_ M2I_Byrack_IsPostTm_IMM24_04 : 32|8@1+ (0.01,0) [0|2.55] "s"  IMM
 SG_ M2I_Byrack_SysABStTm_IMM24_04 : 40|16@1+ (0.01,0) [0|655.35] "s"  IMM
 SG_ Reserved_04 : 56|8@1+ (1,0) [0|255] ""  IMM

BO_ 2332113045 M2I_Byrack_SUMDATA24__05: 8 MBMU
 SG_ CRC_M2I_Byrack_IMM24_05 : 0|8@1+ (1,0) [0|255] ""  IMM
 SG_ M2I_Byrack_HVS_IMM24_05 : 8|16@1+ (0.1,0) [0|6553.5] "v"  IMM
 SG_ M2I_Byrack_Enable_IMM24_05 : 24|2@1+ (1,0) [0|3] ""  IMM
 SG_ M2I_Byrack_ReVeEnable_IMM24_05 : 26|2@1+ (1,0) [0|3] ""  IMM
 SG_ Reserved_05 : 28|4@1+ (1,0) [0|15] ""  IMM
 SG_ M2I_Byrack_IsPostTm_IMM24_05 : 32|8@1+ (0.01,0) [0|2.55] "s"  IMM
 SG_ M2I_Byrack_SysABStTm_IMM24_05 : 40|16@1+ (0.01,0) [0|655.35] "s"  IMM
 SG_ Reserved_05 : 56|8@1+ (1,0) [0|255] ""  IMM

BO_ 2332113046 M2I_Byrack_SUMDATA24__06: 8 MBMU
 SG_ CRC_M2I_Byrack_IMM24_06 : 0|8@1+ (1,0) [0|255] ""  IMM
 SG_ M2I_Byrack_HVS_IMM24_06 : 8|16@1+ (0.1,0) [0|6553.5] "v"  IMM
 SG_ M2I_Byrack_Enable_IMM24_06 : 24|2@1+ (1,0) [0|3] ""  IMM
 SG_ M2I_Byrack_ReVeEnable_IMM24_06 : 26|2@1+ (1,0) [0|3] ""  IMM
 SG_ Reserved_06 : 28|4@1+ (1,0) [0|15] ""  IMM
 SG_ M2I_Byrack_IsPostTm_IMM24_06 : 32|8@1+ (0.01,0) [0|2.55] "s"  IMM
 SG_ M2I_Byrack_SysABStTm_IMM24_06 : 40|16@1+ (0.01,0) [0|655.35] "s"  IMM
 SG_ Reserved_06 : 56|8@1+ (1,0) [0|255] ""  IMM

BO_ 2332113047 M2I_Byrack_SUMDATA24__07: 8 MBMU
 SG_ CRC_M2I_Byrack_IMM24_07 : 0|8@1+ (1,0) [0|255] ""  IMM
 SG_ M2I_Byrack_HVS_IMM24_07 : 8|16@1+ (0.1,0) [0|6553.5] "v"  IMM
 SG_ M2I_Byrack_Enable_IMM24_07 : 24|2@1+ (1,0) [0|3] ""  IMM
 SG_ M2I_Byrack_ReVeEnable_IMM24_07 : 26|2@1+ (1,0) [0|3] ""  IMM
 SG_ Reserved_07 : 28|4@1+ (1,0) [0|15] ""  IMM
 SG_ M2I_Byrack_IsPostTm_IMM24_07 : 32|8@1+ (0.01,0) [0|2.55] "s"  IMM
 SG_ M2I_Byrack_SysABStTm_IMM24_07 : 40|16@1+ (0.01,0) [0|655.35] "s"  IMM
 SG_ Reserved_07 : 56|8@1+ (1,0) [0|255] ""  IMM

BO_ 2332113048 M2I_Byrack_SUMDATA24__08: 8 MBMU
 SG_ CRC_M2I_Byrack_IMM24_08 : 0|8@1+ (1,0) [0|255] ""  IMM
 SG_ M2I_Byrack_HVS_IMM24_08 : 8|16@1+ (0.1,0) [0|6553.5] "v"  IMM
 SG_ M2I_Byrack_Enable_IMM24_08 : 24|2@1+ (1,0) [0|3] ""  IMM
 SG_ M2I_Byrack_ReVeEnable_IMM24_08 : 26|2@1+ (1,0) [0|3] ""  IMM
 SG_ Reserved_08 : 28|4@1+ (1,0) [0|15] ""  IMM
 SG_ M2I_Byrack_IsPostTm_IMM24_08 : 32|8@1+ (0.01,0) [0|2.55] "s"  IMM
 SG_ M2I_Byrack_SysABStTm_IMM24_08 : 40|16@1+ (0.01,0) [0|655.35] "s"  IMM
 SG_ Reserved_08 : 56|8@1+ (1,0) [0|255] ""  IMM

BO_ 2332113049 M2I_Byrack_SUMDATA24__09: 8 MBMU
 SG_ CRC_M2I_Byrack_IMM24_09 : 0|8@1+ (1,0) [0|255] ""  IMM
 SG_ M2I_Byrack_HVS_IMM24_09 : 8|16@1+ (0.1,0) [0|6553.5] "v"  IMM
 SG_ M2I_Byrack_Enable_IMM24_09 : 24|2@1+ (1,0) [0|3] ""  IMM
 SG_ M2I_Byrack_ReVeEnable_IMM24_09 : 26|2@1+ (1,0) [0|3] ""  IMM
 SG_ Reserved_09 : 28|4@1+ (1,0) [0|15] ""  IMM
 SG_ M2I_Byrack_IsPostTm_IMM24_09 : 32|8@1+ (0.01,0) [0|2.55] "s"  IMM
 SG_ M2I_Byrack_SysABStTm_IMM24_09 : 40|16@1+ (0.01,0) [0|655.35] "s"  IMM
 SG_ Reserved_09 : 56|8@1+ (1,0) [0|255] ""  IMM

BO_ 2332113050 M2I_Byrack_SUMDATA24__10: 8 MBMU
 SG_ CRC_M2I_Byrack_IMM24_10 : 0|8@1+ (1,0) [0|255] ""  IMM
 SG_ M2I_Byrack_HVS_IMM24_10 : 8|16@1+ (0.1,0) [0|6553.5] "v"  IMM
 SG_ M2I_Byrack_Enable_IMM24_10 : 24|2@1+ (1,0) [0|3] ""  IMM
 SG_ M2I_Byrack_ReVeEnable_IMM24_10 : 26|2@1+ (1,0) [0|3] ""  IMM
 SG_ Reserved_10 : 28|4@1+ (1,0) [0|15] ""  IMM
 SG_ M2I_Byrack_IsPostTm_IMM24_10 : 32|8@1+ (0.01,0) [0|2.55] "s"  IMM
 SG_ M2I_Byrack_SysABStTm_IMM24_10 : 40|16@1+ (0.01,0) [0|655.35] "s"  IMM
 SG_ Reserved_10 : 56|8@1+ (1,0) [0|255] ""  IMM

BO_ 2332113051 M2I_Byrack_SUMDATA24__11: 8 MBMU
 SG_ CRC_M2I_Byrack_IMM24_11 : 0|8@1+ (1,0) [0|255] ""  IMM
 SG_ M2I_Byrack_HVS_IMM24_11 : 8|16@1+ (0.1,0) [0|6553.5] "v"  IMM
 SG_ M2I_Byrack_Enable_IMM24_11 : 24|2@1+ (1,0) [0|3] ""  IMM
 SG_ M2I_Byrack_ReVeEnable_IMM24_11 : 26|2@1+ (1,0) [0|3] ""  IMM
 SG_ Reserved_11 : 28|4@1+ (1,0) [0|15] ""  IMM
 SG_ M2I_Byrack_IsPostTm_IMM24_11 : 32|8@1+ (0.01,0) [0|2.55] "s"  IMM
 SG_ M2I_Byrack_SysABStTm_IMM24_11 : 40|16@1+ (0.01,0) [0|655.35] "s"  IMM
 SG_ Reserved_11 : 56|8@1+ (1,0) [0|255] ""  IMM

BO_ 2332113052 M2I_Byrack_SUMDATA24__12: 8 MBMU
 SG_ CRC_M2I_Byrack_IMM24_12 : 0|8@1+ (1,0) [0|255] ""  IMM
 SG_ M2I_Byrack_HVS_IMM24_12 : 8|16@1+ (0.1,0) [0|6553.5] "v"  IMM
 SG_ M2I_Byrack_Enable_IMM24_12 : 24|2@1+ (1,0) [0|3] ""  IMM
 SG_ M2I_Byrack_ReVeEnable_IMM24_12 : 26|2@1+ (1,0) [0|3] ""  IMM
 SG_ Reserved_12 : 28|4@1+ (1,0) [0|15] ""  IMM
 SG_ M2I_Byrack_IsPostTm_IMM24_12 : 32|8@1+ (0.01,0) [0|2.55] "s"  IMM
 SG_ M2I_Byrack_SysABStTm_IMM24_12 : 40|16@1+ (0.01,0) [0|655.35] "s"  IMM
 SG_ Reserved_12 : 56|8@1+ (1,0) [0|255] ""  IMM

BO_ 2332113053 M2I_Byrack_SUMDATA24__13: 8 MBMU
 SG_ CRC_M2I_Byrack_IMM24_13 : 0|8@1+ (1,0) [0|255] ""  IMM
 SG_ M2I_Byrack_HVS_IMM24_13 : 8|16@1+ (0.1,0) [0|6553.5] "v"  IMM
 SG_ M2I_Byrack_Enable_IMM24_13 : 24|2@1+ (1,0) [0|3] ""  IMM
 SG_ M2I_Byrack_ReVeEnable_IMM24_13 : 26|2@1+ (1,0) [0|3] ""  IMM
 SG_ Reserved_13 : 28|4@1+ (1,0) [0|15] ""  IMM
 SG_ M2I_Byrack_IsPostTm_IMM24_13 : 32|8@1+ (0.01,0) [0|2.55] "s"  IMM
 SG_ M2I_Byrack_SysABStTm_IMM24_13 : 40|16@1+ (0.01,0) [0|655.35] "s"  IMM
 SG_ Reserved_13 : 56|8@1+ (1,0) [0|255] ""  IMM

BO_ 2332113054 M2I_Byrack_SUMDATA24__14: 8 MBMU
 SG_ CRC_M2I_Byrack_IMM24_14 : 0|8@1+ (1,0) [0|255] ""  IMM
 SG_ M2I_Byrack_HVS_IMM24_14 : 8|16@1+ (0.1,0) [0|6553.5] "v"  IMM
 SG_ M2I_Byrack_Enable_IMM24_14 : 24|2@1+ (1,0) [0|3] ""  IMM
 SG_ M2I_Byrack_ReVeEnable_IMM24_14 : 26|2@1+ (1,0) [0|3] ""  IMM
 SG_ Reserved_14 : 28|4@1+ (1,0) [0|15] ""  IMM
 SG_ M2I_Byrack_IsPostTm_IMM24_14 : 32|8@1+ (0.01,0) [0|2.55] "s"  IMM
 SG_ M2I_Byrack_SysABStTm_IMM24_14 : 40|16@1+ (0.01,0) [0|655.35] "s"  IMM
 SG_ Reserved_14 : 56|8@1+ (1,0) [0|255] ""  IMM

BO_ 2332113055 M2I_Byrack_SUMDATA24__15: 8 MBMU
 SG_ CRC_M2I_Byrack_IMM24_15 : 0|8@1+ (1,0) [0|255] ""  IMM
 SG_ M2I_Byrack_HVS_IMM24_15 : 8|16@1+ (0.1,0) [0|6553.5] "v"  IMM
 SG_ M2I_Byrack_Enable_IMM24_15 : 24|2@1+ (1,0) [0|3] ""  IMM
 SG_ M2I_Byrack_ReVeEnable_IMM24_15 : 26|2@1+ (1,0) [0|3] ""  IMM
 SG_ Reserved_15 : 28|4@1+ (1,0) [0|15] ""  IMM
 SG_ M2I_Byrack_IsPostTm_IMM24_15 : 32|8@1+ (0.01,0) [0|2.55] "s"  IMM
 SG_ M2I_Byrack_SysABStTm_IMM24_15 : 40|16@1+ (0.01,0) [0|655.35] "s"  IMM
 SG_ Reserved_15 : 56|8@1+ (1,0) [0|255] ""  IMM

BO_ 2332113056 M2I_Byrack_SUMDATA24__16: 8 MBMU
 SG_ CRC_M2I_Byrack_IMM24_16 : 0|8@1+ (1,0) [0|255] ""  IMM
 SG_ M2I_Byrack_HVS_IMM24_16 : 8|16@1+ (0.1,0) [0|6553.5] "v"  IMM
 SG_ M2I_Byrack_Enable_IMM24_16 : 24|2@1+ (1,0) [0|3] ""  IMM
 SG_ M2I_Byrack_ReVeEnable_IMM24_16 : 26|2@1+ (1,0) [0|3] ""  IMM
 SG_ Reserved_16 : 28|4@1+ (1,0) [0|15] ""  IMM
 SG_ M2I_Byrack_IsPostTm_IMM24_16 : 32|8@1+ (0.01,0) [0|2.55] "s"  IMM
 SG_ M2I_Byrack_SysABStTm_IMM24_16 : 40|16@1+ (0.01,0) [0|655.35] "s"  IMM
 SG_ Reserved_16 : 56|8@1+ (1,0) [0|255] ""  IMM

BO_ 2332113057 M2I_Byrack_SUMDATA24__17: 8 MBMU
 SG_ CRC_M2I_Byrack_IMM24_17 : 0|8@1+ (1,0) [0|255] ""  IMM
 SG_ M2I_Byrack_HVS_IMM24_17 : 8|16@1+ (0.1,0) [0|6553.5] "v"  IMM
 SG_ M2I_Byrack_Enable_IMM24_17 : 24|2@1+ (1,0) [0|3] ""  IMM
 SG_ M2I_Byrack_ReVeEnable_IMM24_17 : 26|2@1+ (1,0) [0|3] ""  IMM
 SG_ Reserved_17 : 28|4@1+ (1,0) [0|15] ""  IMM
 SG_ M2I_Byrack_IsPostTm_IMM24_17 : 32|8@1+ (0.01,0) [0|2.55] "s"  IMM
 SG_ M2I_Byrack_SysABStTm_IMM24_17 : 40|16@1+ (0.01,0) [0|655.35] "s"  IMM
 SG_ Reserved_17 : 56|8@1+ (1,0) [0|255] ""  IMM

BO_ 2332113058 M2I_Byrack_SUMDATA24__18: 8 MBMU
 SG_ CRC_M2I_Byrack_IMM24_18 : 0|8@1+ (1,0) [0|255] ""  IMM
 SG_ M2I_Byrack_HVS_IMM24_18 : 8|16@1+ (0.1,0) [0|6553.5] "v"  IMM
 SG_ M2I_Byrack_Enable_IMM24_18 : 24|2@1+ (1,0) [0|3] ""  IMM
 SG_ M2I_Byrack_ReVeEnable_IMM24_18 : 26|2@1+ (1,0) [0|3] ""  IMM
 SG_ Reserved_18 : 28|4@1+ (1,0) [0|15] ""  IMM
 SG_ M2I_Byrack_IsPostTm_IMM24_18 : 32|8@1+ (0.01,0) [0|2.55] "s"  IMM
 SG_ M2I_Byrack_SysABStTm_IMM24_18 : 40|16@1+ (0.01,0) [0|655.35] "s"  IMM
 SG_ Reserved_18 : 56|8@1+ (1,0) [0|255] ""  IMM

BO_ 2332113059 M2I_Byrack_SUMDATA24__19: 8 MBMU
 SG_ CRC_M2I_Byrack_IMM24_19 : 0|8@1+ (1,0) [0|255] ""  IMM
 SG_ M2I_Byrack_HVS_IMM24_19 : 8|16@1+ (0.1,0) [0|6553.5] "v"  IMM
 SG_ M2I_Byrack_Enable_IMM24_19 : 24|2@1+ (1,0) [0|3] ""  IMM
 SG_ M2I_Byrack_ReVeEnable_IMM24_19 : 26|2@1+ (1,0) [0|3] ""  IMM
 SG_ Reserved_19 : 28|4@1+ (1,0) [0|15] ""  IMM
 SG_ M2I_Byrack_IsPostTm_IMM24_19 : 32|8@1+ (0.01,0) [0|2.55] "s"  IMM
 SG_ M2I_Byrack_SysABStTm_IMM24_19 : 40|16@1+ (0.01,0) [0|655.35] "s"  IMM
 SG_ Reserved_19 : 56|8@1+ (1,0) [0|255] ""  IMM

BO_ 2332113060 M2I_Byrack_SUMDATA24__20: 8 MBMU
 SG_ CRC_M2I_Byrack_IMM24_20 : 0|8@1+ (1,0) [0|255] ""  IMM
 SG_ M2I_Byrack_HVS_IMM24_20 : 8|16@1+ (0.1,0) [0|6553.5] "v"  IMM
 SG_ M2I_Byrack_Enable_IMM24_20 : 24|2@1+ (1,0) [0|3] ""  IMM
 SG_ M2I_Byrack_ReVeEnable_IMM24_20 : 26|2@1+ (1,0) [0|3] ""  IMM
 SG_ Reserved_20 : 28|4@1+ (1,0) [0|15] ""  IMM
 SG_ M2I_Byrack_IsPostTm_IMM24_20 : 32|8@1+ (0.01,0) [0|2.55] "s"  IMM
 SG_ M2I_Byrack_SysABStTm_IMM24_20 : 40|16@1+ (0.01,0) [0|655.35] "s"  IMM
 SG_ Reserved_20 : 56|8@1+ (1,0) [0|255] ""  IMM

BO_ 2332113061 M2I_Byrack_SUMDATA24__21: 8 MBMU
 SG_ CRC_M2I_Byrack_IMM24_21 : 0|8@1+ (1,0) [0|255] ""  IMM
 SG_ M2I_Byrack_HVS_IMM24_21 : 8|16@1+ (0.1,0) [0|6553.5] "v"  IMM
 SG_ M2I_Byrack_Enable_IMM24_21 : 24|2@1+ (1,0) [0|3] ""  IMM
 SG_ M2I_Byrack_ReVeEnable_IMM24_21 : 26|2@1+ (1,0) [0|3] ""  IMM
 SG_ Reserved_21 : 28|4@1+ (1,0) [0|15] ""  IMM
 SG_ M2I_Byrack_IsPostTm_IMM24_21 : 32|8@1+ (0.01,0) [0|2.55] "s"  IMM
 SG_ M2I_Byrack_SysABStTm_IMM24_21 : 40|16@1+ (0.01,0) [0|655.35] "s"  IMM
 SG_ Reserved_21 : 56|8@1+ (1,0) [0|255] ""  IMM

BO_ 2332113062 M2I_Byrack_SUMDATA24__22: 8 MBMU
 SG_ CRC_M2I_Byrack_IMM24_22 : 0|8@1+ (1,0) [0|255] ""  IMM
 SG_ M2I_Byrack_HVS_IMM24_22 : 8|16@1+ (0.1,0) [0|6553.5] "v"  IMM
 SG_ M2I_Byrack_Enable_IMM24_22 : 24|2@1+ (1,0) [0|3] ""  IMM
 SG_ M2I_Byrack_ReVeEnable_IMM24_22 : 26|2@1+ (1,0) [0|3] ""  IMM
 SG_ Reserved_22 : 28|4@1+ (1,0) [0|15] ""  IMM
 SG_ M2I_Byrack_IsPostTm_IMM24_22 : 32|8@1+ (0.01,0) [0|2.55] "s"  IMM
 SG_ M2I_Byrack_SysABStTm_IMM24_22 : 40|16@1+ (0.01,0) [0|655.35] "s"  IMM
 SG_ Reserved_22 : 56|8@1+ (1,0) [0|255] ""  IMM

BO_ 2332113063 M2I_Byrack_SUMDATA24__23: 8 MBMU
 SG_ CRC_M2I_Byrack_IMM24_23 : 0|8@1+ (1,0) [0|255] ""  IMM
 SG_ M2I_Byrack_HVS_IMM24_23 : 8|16@1+ (0.1,0) [0|6553.5] "v"  IMM
 SG_ M2I_Byrack_Enable_IMM24_23 : 24|2@1+ (1,0) [0|3] ""  IMM
 SG_ M2I_Byrack_ReVeEnable_IMM24_23 : 26|2@1+ (1,0) [0|3] ""  IMM
 SG_ Reserved_23 : 28|4@1+ (1,0) [0|15] ""  IMM
 SG_ M2I_Byrack_IsPostTm_IMM24_23 : 32|8@1+ (0.01,0) [0|2.55] "s"  IMM
 SG_ M2I_Byrack_SysABStTm_IMM24_23 : 40|16@1+ (0.01,0) [0|655.35] "s"  IMM
 SG_ Reserved_23 : 56|8@1+ (1,0) [0|255] ""  IMM

BO_ 2332113064 M2I_Byrack_SUMDATA24__24: 8 MBMU
 SG_ CRC_M2I_Byrack_IMM24_24 : 0|8@1+ (1,0) [0|255] ""  IMM
 SG_ M2I_Byrack_HVS_IMM24_24 : 8|16@1+ (0.1,0) [0|6553.5] "v"  IMM
 SG_ M2I_Byrack_Enable_IMM24_24 : 24|2@1+ (1,0) [0|3] ""  IMM
 SG_ M2I_Byrack_ReVeEnable_IMM24_24 : 26|2@1+ (1,0) [0|3] ""  IMM
 SG_ Reserved_24 : 28|4@1+ (1,0) [0|15] ""  IMM
 SG_ M2I_Byrack_IsPostTm_IMM24_24 : 32|8@1+ (0.01,0) [0|2.55] "s"  IMM
 SG_ M2I_Byrack_SysABStTm_IMM24_24 : 40|16@1+ (0.01,0) [0|655.35] "s"  IMM
 SG_ Reserved_24 : 56|8@1+ (1,0) [0|255] ""  IMM

BO_ 2332113065 M2I_Byrack_SUMDATA24__25: 8 MBMU
 SG_ CRC_M2I_Byrack_IMM24_25 : 0|8@1+ (1,0) [0|255] ""  IMM
 SG_ M2I_Byrack_HVS_IMM24_25 : 8|16@1+ (0.1,0) [0|6553.5] "v"  IMM
 SG_ M2I_Byrack_Enable_IMM24_25 : 24|2@1+ (1,0) [0|3] ""  IMM
 SG_ M2I_Byrack_ReVeEnable_IMM24_25 : 26|2@1+ (1,0) [0|3] ""  IMM
 SG_ Reserved_25 : 28|4@1+ (1,0) [0|15] ""  IMM
 SG_ M2I_Byrack_IsPostTm_IMM24_25 : 32|8@1+ (0.01,0) [0|2.55] "s"  IMM
 SG_ M2I_Byrack_SysABStTm_IMM24_25 : 40|16@1+ (0.01,0) [0|655.35] "s"  IMM
 SG_ Reserved_25 : 56|8@1+ (1,0) [0|255] ""  IMM

BO_ 2332113066 M2I_Byrack_SUMDATA24__26: 8 MBMU
 SG_ CRC_M2I_Byrack_IMM24_26 : 0|8@1+ (1,0) [0|255] ""  IMM
 SG_ M2I_Byrack_HVS_IMM24_26 : 8|16@1+ (0.1,0) [0|6553.5] "v"  IMM
 SG_ M2I_Byrack_Enable_IMM24_26 : 24|2@1+ (1,0) [0|3] ""  IMM
 SG_ M2I_Byrack_ReVeEnable_IMM24_26 : 26|2@1+ (1,0) [0|3] ""  IMM
 SG_ Reserved_26 : 28|4@1+ (1,0) [0|15] ""  IMM
 SG_ M2I_Byrack_IsPostTm_IMM24_26 : 32|8@1+ (0.01,0) [0|2.55] "s"  IMM
 SG_ M2I_Byrack_SysABStTm_IMM24_26 : 40|16@1+ (0.01,0) [0|655.35] "s"  IMM
 SG_ Reserved_26 : 56|8@1+ (1,0) [0|255] ""  IMM

BO_ 2332113067 M2I_Byrack_SUMDATA24__27: 8 MBMU
 SG_ CRC_M2I_Byrack_IMM24_27 : 0|8@1+ (1,0) [0|255] ""  IMM
 SG_ M2I_Byrack_HVS_IMM24_27 : 8|16@1+ (0.1,0) [0|6553.5] "v"  IMM
 SG_ M2I_Byrack_Enable_IMM24_27 : 24|2@1+ (1,0) [0|3] ""  IMM
 SG_ M2I_Byrack_ReVeEnable_IMM24_27 : 26|2@1+ (1,0) [0|3] ""  IMM
 SG_ Reserved_27 : 28|4@1+ (1,0) [0|15] ""  IMM
 SG_ M2I_Byrack_IsPostTm_IMM24_27 : 32|8@1+ (0.01,0) [0|2.55] "s"  IMM
 SG_ M2I_Byrack_SysABStTm_IMM24_27 : 40|16@1+ (0.01,0) [0|655.35] "s"  IMM
 SG_ Reserved_27 : 56|8@1+ (1,0) [0|255] ""  IMM

BO_ 2332113068 M2I_Byrack_SUMDATA24__28: 8 MBMU
 SG_ CRC_M2I_Byrack_IMM24_28 : 0|8@1+ (1,0) [0|255] ""  IMM
 SG_ M2I_Byrack_HVS_IMM24_28 : 8|16@1+ (0.1,0) [0|6553.5] "v"  IMM
 SG_ M2I_Byrack_Enable_IMM24_28 : 24|2@1+ (1,0) [0|3] ""  IMM
 SG_ M2I_Byrack_ReVeEnable_IMM24_28 : 26|2@1+ (1,0) [0|3] ""  IMM
 SG_ Reserved_28 : 28|4@1+ (1,0) [0|15] ""  IMM
 SG_ M2I_Byrack_IsPostTm_IMM24_28 : 32|8@1+ (0.01,0) [0|2.55] "s"  IMM
 SG_ M2I_Byrack_SysABStTm_IMM24_28 : 40|16@1+ (0.01,0) [0|655.35] "s"  IMM
 SG_ Reserved_28 : 56|8@1+ (1,0) [0|255] ""  IMM

BO_ 2332113069 M2I_Byrack_SUMDATA24__29: 8 MBMU
 SG_ CRC_M2I_Byrack_IMM24_29 : 0|8@1+ (1,0) [0|255] ""  IMM
 SG_ M2I_Byrack_HVS_IMM24_29 : 8|16@1+ (0.1,0) [0|6553.5] "v"  IMM
 SG_ M2I_Byrack_Enable_IMM24_29 : 24|2@1+ (1,0) [0|3] ""  IMM
 SG_ M2I_Byrack_ReVeEnable_IMM24_29 : 26|2@1+ (1,0) [0|3] ""  IMM
 SG_ Reserved_29 : 28|4@1+ (1,0) [0|15] ""  IMM
 SG_ M2I_Byrack_IsPostTm_IMM24_29 : 32|8@1+ (0.01,0) [0|2.55] "s"  IMM
 SG_ M2I_Byrack_SysABStTm_IMM24_29 : 40|16@1+ (0.01,0) [0|655.35] "s"  IMM
 SG_ Reserved_29 : 56|8@1+ (1,0) [0|255] ""  IMM

BO_ 2332113070 M2I_Byrack_SUMDATA24__30: 8 MBMU
 SG_ CRC_M2I_Byrack_IMM24_30 : 0|8@1+ (1,0) [0|255] ""  IMM
 SG_ M2I_Byrack_HVS_IMM24_30 : 8|16@1+ (0.1,0) [0|6553.5] "v"  IMM
 SG_ M2I_Byrack_Enable_IMM24_30 : 24|2@1+ (1,0) [0|3] ""  IMM
 SG_ M2I_Byrack_ReVeEnable_IMM24_30 : 26|2@1+ (1,0) [0|3] ""  IMM
 SG_ Reserved_30 : 28|4@1+ (1,0) [0|15] ""  IMM
 SG_ M2I_Byrack_IsPostTm_IMM24_30 : 32|8@1+ (0.01,0) [0|2.55] "s"  IMM
 SG_ M2I_Byrack_SysABStTm_IMM24_30 : 40|16@1+ (0.01,0) [0|655.35] "s"  IMM
 SG_ Reserved_30 : 56|8@1+ (1,0) [0|255] ""  IMM

BO_ 2332113071 M2I_Byrack_SUMDATA24__31: 8 MBMU
 SG_ CRC_M2I_Byrack_IMM24_31 : 0|8@1+ (1,0) [0|255] ""  IMM
 SG_ M2I_Byrack_HVS_IMM24_31 : 8|16@1+ (0.1,0) [0|6553.5] "v"  IMM
 SG_ M2I_Byrack_Enable_IMM24_31 : 24|2@1+ (1,0) [0|3] ""  IMM
 SG_ M2I_Byrack_ReVeEnable_IMM24_31 : 26|2@1+ (1,0) [0|3] ""  IMM
 SG_ Reserved_31 : 28|4@1+ (1,0) [0|15] ""  IMM
 SG_ M2I_Byrack_IsPostTm_IMM24_31 : 32|8@1+ (0.01,0) [0|2.55] "s"  IMM
 SG_ M2I_Byrack_SysABStTm_IMM24_31 : 40|16@1+ (0.01,0) [0|655.35] "s"  IMM
 SG_ Reserved_31 : 56|8@1+ (1,0) [0|255] ""  IMM

BO_ 2332113297 M2I_Byrack_SUMDATA25__01: 8 MBMU
 SG_ CRC_M2I_Byrack_IMM25_01 : 0|8@1+ (1,0) [0|255] ""  IMM
 SG_ M2I_Byrack_HVS_IMM25_01 : 8|16@1+ (0.1,0) [0|6553.5] "v"  IMM
 SG_ M2I_Byrack_Enable_IMM25_01 : 24|2@1+ (1,0) [0|3] ""  IMM
 SG_ M2I_Byrack_ReVeEnable_IMM25_01 : 26|2@1+ (1,0) [0|3] ""  IMM
 SG_ Reserved_01 : 28|4@1+ (1,0) [0|15] ""  IMM
 SG_ M2I_Byrack_IsPostTm_IMM25_01 : 32|8@1+ (0.01,0) [0|2.55] "s"  IMM
 SG_ M2I_Byrack_SysABStTm_IMM25_01 : 40|16@1+ (0.01,0) [0|655.35] "s"  IMM
 SG_ Reserved_01 : 56|8@1+ (1,0) [0|255] ""  IMM

BO_ 2332113298 M2I_Byrack_SUMDATA25__02: 8 MBMU
 SG_ CRC_M2I_Byrack_IMM25_02 : 0|8@1+ (1,0) [0|255] ""  IMM
 SG_ M2I_Byrack_HVS_IMM25_02 : 8|16@1+ (0.1,0) [0|6553.5] "v"  IMM
 SG_ M2I_Byrack_Enable_IMM25_02 : 24|2@1+ (1,0) [0|3] ""  IMM
 SG_ M2I_Byrack_ReVeEnable_IMM25_02 : 26|2@1+ (1,0) [0|3] ""  IMM
 SG_ Reserved_02 : 28|4@1+ (1,0) [0|15] ""  IMM
 SG_ M2I_Byrack_IsPostTm_IMM25_02 : 32|8@1+ (0.01,0) [0|2.55] "s"  IMM
 SG_ M2I_Byrack_SysABStTm_IMM25_02 : 40|16@1+ (0.01,0) [0|655.35] "s"  IMM
 SG_ Reserved_02 : 56|8@1+ (1,0) [0|255] ""  IMM

BO_ 2332113299 M2I_Byrack_SUMDATA25__03: 8 MBMU
 SG_ CRC_M2I_Byrack_IMM25_03 : 0|8@1+ (1,0) [0|255] ""  IMM
 SG_ M2I_Byrack_HVS_IMM25_03 : 8|16@1+ (0.1,0) [0|6553.5] "v"  IMM
 SG_ M2I_Byrack_Enable_IMM25_03 : 24|2@1+ (1,0) [0|3] ""  IMM
 SG_ M2I_Byrack_ReVeEnable_IMM25_03 : 26|2@1+ (1,0) [0|3] ""  IMM
 SG_ Reserved_03 : 28|4@1+ (1,0) [0|15] ""  IMM
 SG_ M2I_Byrack_IsPostTm_IMM25_03 : 32|8@1+ (0.01,0) [0|2.55] "s"  IMM
 SG_ M2I_Byrack_SysABStTm_IMM25_03 : 40|16@1+ (0.01,0) [0|655.35] "s"  IMM
 SG_ Reserved_03 : 56|8@1+ (1,0) [0|255] ""  IMM

BO_ 2332113300 M2I_Byrack_SUMDATA25__04: 8 MBMU
 SG_ CRC_M2I_Byrack_IMM25_04 : 0|8@1+ (1,0) [0|255] ""  IMM
 SG_ M2I_Byrack_HVS_IMM25_04 : 8|16@1+ (0.1,0) [0|6553.5] "v"  IMM
 SG_ M2I_Byrack_Enable_IMM25_04 : 24|2@1+ (1,0) [0|3] ""  IMM
 SG_ M2I_Byrack_ReVeEnable_IMM25_04 : 26|2@1+ (1,0) [0|3] ""  IMM
 SG_ Reserved_04 : 28|4@1+ (1,0) [0|15] ""  IMM
 SG_ M2I_Byrack_IsPostTm_IMM25_04 : 32|8@1+ (0.01,0) [0|2.55] "s"  IMM
 SG_ M2I_Byrack_SysABStTm_IMM25_04 : 40|16@1+ (0.01,0) [0|655.35] "s"  IMM
 SG_ Reserved_04 : 56|8@1+ (1,0) [0|255] ""  IMM

BO_ 2332113301 M2I_Byrack_SUMDATA25__05: 8 MBMU
 SG_ CRC_M2I_Byrack_IMM25_05 : 0|8@1+ (1,0) [0|255] ""  IMM
 SG_ M2I_Byrack_HVS_IMM25_05 : 8|16@1+ (0.1,0) [0|6553.5] "v"  IMM
 SG_ M2I_Byrack_Enable_IMM25_05 : 24|2@1+ (1,0) [0|3] ""  IMM
 SG_ M2I_Byrack_ReVeEnable_IMM25_05 : 26|2@1+ (1,0) [0|3] ""  IMM
 SG_ Reserved_05 : 28|4@1+ (1,0) [0|15] ""  IMM
 SG_ M2I_Byrack_IsPostTm_IMM25_05 : 32|8@1+ (0.01,0) [0|2.55] "s"  IMM
 SG_ M2I_Byrack_SysABStTm_IMM25_05 : 40|16@1+ (0.01,0) [0|655.35] "s"  IMM
 SG_ Reserved_05 : 56|8@1+ (1,0) [0|255] ""  IMM

BO_ 2332113302 M2I_Byrack_SUMDATA25__06: 8 MBMU
 SG_ CRC_M2I_Byrack_IMM25_06 : 0|8@1+ (1,0) [0|255] ""  IMM
 SG_ M2I_Byrack_HVS_IMM25_06 : 8|16@1+ (0.1,0) [0|6553.5] "v"  IMM
 SG_ M2I_Byrack_Enable_IMM25_06 : 24|2@1+ (1,0) [0|3] ""  IMM
 SG_ M2I_Byrack_ReVeEnable_IMM25_06 : 26|2@1+ (1,0) [0|3] ""  IMM
 SG_ Reserved_06 : 28|4@1+ (1,0) [0|15] ""  IMM
 SG_ M2I_Byrack_IsPostTm_IMM25_06 : 32|8@1+ (0.01,0) [0|2.55] "s"  IMM
 SG_ M2I_Byrack_SysABStTm_IMM25_06 : 40|16@1+ (0.01,0) [0|655.35] "s"  IMM
 SG_ Reserved_06 : 56|8@1+ (1,0) [0|255] ""  IMM

BO_ 2332113303 M2I_Byrack_SUMDATA25__07: 8 MBMU
 SG_ CRC_M2I_Byrack_IMM25_07 : 0|8@1+ (1,0) [0|255] ""  IMM
 SG_ M2I_Byrack_HVS_IMM25_07 : 8|16@1+ (0.1,0) [0|6553.5] "v"  IMM
 SG_ M2I_Byrack_Enable_IMM25_07 : 24|2@1+ (1,0) [0|3] ""  IMM
 SG_ M2I_Byrack_ReVeEnable_IMM25_07 : 26|2@1+ (1,0) [0|3] ""  IMM
 SG_ Reserved_07 : 28|4@1+ (1,0) [0|15] ""  IMM
 SG_ M2I_Byrack_IsPostTm_IMM25_07 : 32|8@1+ (0.01,0) [0|2.55] "s"  IMM
 SG_ M2I_Byrack_SysABStTm_IMM25_07 : 40|16@1+ (0.01,0) [0|655.35] "s"  IMM
 SG_ Reserved_07 : 56|8@1+ (1,0) [0|255] ""  IMM

BO_ 2332113304 M2I_Byrack_SUMDATA25__08: 8 MBMU
 SG_ CRC_M2I_Byrack_IMM25_08 : 0|8@1+ (1,0) [0|255] ""  IMM
 SG_ M2I_Byrack_HVS_IMM25_08 : 8|16@1+ (0.1,0) [0|6553.5] "v"  IMM
 SG_ M2I_Byrack_Enable_IMM25_08 : 24|2@1+ (1,0) [0|3] ""  IMM
 SG_ M2I_Byrack_ReVeEnable_IMM25_08 : 26|2@1+ (1,0) [0|3] ""  IMM
 SG_ Reserved_08 : 28|4@1+ (1,0) [0|15] ""  IMM
 SG_ M2I_Byrack_IsPostTm_IMM25_08 : 32|8@1+ (0.01,0) [0|2.55] "s"  IMM
 SG_ M2I_Byrack_SysABStTm_IMM25_08 : 40|16@1+ (0.01,0) [0|655.35] "s"  IMM
 SG_ Reserved_08 : 56|8@1+ (1,0) [0|255] ""  IMM

BO_ 2332113305 M2I_Byrack_SUMDATA25__09: 8 MBMU
 SG_ CRC_M2I_Byrack_IMM25_09 : 0|8@1+ (1,0) [0|255] ""  IMM
 SG_ M2I_Byrack_HVS_IMM25_09 : 8|16@1+ (0.1,0) [0|6553.5] "v"  IMM
 SG_ M2I_Byrack_Enable_IMM25_09 : 24|2@1+ (1,0) [0|3] ""  IMM
 SG_ M2I_Byrack_ReVeEnable_IMM25_09 : 26|2@1+ (1,0) [0|3] ""  IMM
 SG_ Reserved_09 : 28|4@1+ (1,0) [0|15] ""  IMM
 SG_ M2I_Byrack_IsPostTm_IMM25_09 : 32|8@1+ (0.01,0) [0|2.55] "s"  IMM
 SG_ M2I_Byrack_SysABStTm_IMM25_09 : 40|16@1+ (0.01,0) [0|655.35] "s"  IMM
 SG_ Reserved_09 : 56|8@1+ (1,0) [0|255] ""  IMM

BO_ 2332113306 M2I_Byrack_SUMDATA25__10: 8 MBMU
 SG_ CRC_M2I_Byrack_IMM25_10 : 0|8@1+ (1,0) [0|255] ""  IMM
 SG_ M2I_Byrack_HVS_IMM25_10 : 8|16@1+ (0.1,0) [0|6553.5] "v"  IMM
 SG_ M2I_Byrack_Enable_IMM25_10 : 24|2@1+ (1,0) [0|3] ""  IMM
 SG_ M2I_Byrack_ReVeEnable_IMM25_10 : 26|2@1+ (1,0) [0|3] ""  IMM
 SG_ Reserved_10 : 28|4@1+ (1,0) [0|15] ""  IMM
 SG_ M2I_Byrack_IsPostTm_IMM25_10 : 32|8@1+ (0.01,0) [0|2.55] "s"  IMM
 SG_ M2I_Byrack_SysABStTm_IMM25_10 : 40|16@1+ (0.01,0) [0|655.35] "s"  IMM
 SG_ Reserved_10 : 56|8@1+ (1,0) [0|255] ""  IMM

BO_ 2332113307 M2I_Byrack_SUMDATA25__11: 8 MBMU
 SG_ CRC_M2I_Byrack_IMM25_11 : 0|8@1+ (1,0) [0|255] ""  IMM
 SG_ M2I_Byrack_HVS_IMM25_11 : 8|16@1+ (0.1,0) [0|6553.5] "v"  IMM
 SG_ M2I_Byrack_Enable_IMM25_11 : 24|2@1+ (1,0) [0|3] ""  IMM
 SG_ M2I_Byrack_ReVeEnable_IMM25_11 : 26|2@1+ (1,0) [0|3] ""  IMM
 SG_ Reserved_11 : 28|4@1+ (1,0) [0|15] ""  IMM
 SG_ M2I_Byrack_IsPostTm_IMM25_11 : 32|8@1+ (0.01,0) [0|2.55] "s"  IMM
 SG_ M2I_Byrack_SysABStTm_IMM25_11 : 40|16@1+ (0.01,0) [0|655.35] "s"  IMM
 SG_ Reserved_11 : 56|8@1+ (1,0) [0|255] ""  IMM

BO_ 2332113308 M2I_Byrack_SUMDATA25__12: 8 MBMU
 SG_ CRC_M2I_Byrack_IMM25_12 : 0|8@1+ (1,0) [0|255] ""  IMM
 SG_ M2I_Byrack_HVS_IMM25_12 : 8|16@1+ (0.1,0) [0|6553.5] "v"  IMM
 SG_ M2I_Byrack_Enable_IMM25_12 : 24|2@1+ (1,0) [0|3] ""  IMM
 SG_ M2I_Byrack_ReVeEnable_IMM25_12 : 26|2@1+ (1,0) [0|3] ""  IMM
 SG_ Reserved_12 : 28|4@1+ (1,0) [0|15] ""  IMM
 SG_ M2I_Byrack_IsPostTm_IMM25_12 : 32|8@1+ (0.01,0) [0|2.55] "s"  IMM
 SG_ M2I_Byrack_SysABStTm_IMM25_12 : 40|16@1+ (0.01,0) [0|655.35] "s"  IMM
 SG_ Reserved_12 : 56|8@1+ (1,0) [0|255] ""  IMM

BO_ 2332113309 M2I_Byrack_SUMDATA25__13: 8 MBMU
 SG_ CRC_M2I_Byrack_IMM25_13 : 0|8@1+ (1,0) [0|255] ""  IMM
 SG_ M2I_Byrack_HVS_IMM25_13 : 8|16@1+ (0.1,0) [0|6553.5] "v"  IMM
 SG_ M2I_Byrack_Enable_IMM25_13 : 24|2@1+ (1,0) [0|3] ""  IMM
 SG_ M2I_Byrack_ReVeEnable_IMM25_13 : 26|2@1+ (1,0) [0|3] ""  IMM
 SG_ Reserved_13 : 28|4@1+ (1,0) [0|15] ""  IMM
 SG_ M2I_Byrack_IsPostTm_IMM25_13 : 32|8@1+ (0.01,0) [0|2.55] "s"  IMM
 SG_ M2I_Byrack_SysABStTm_IMM25_13 : 40|16@1+ (0.01,0) [0|655.35] "s"  IMM
 SG_ Reserved_13 : 56|8@1+ (1,0) [0|255] ""  IMM

BO_ 2332113310 M2I_Byrack_SUMDATA25__14: 8 MBMU
 SG_ CRC_M2I_Byrack_IMM25_14 : 0|8@1+ (1,0) [0|255] ""  IMM
 SG_ M2I_Byrack_HVS_IMM25_14 : 8|16@1+ (0.1,0) [0|6553.5] "v"  IMM
 SG_ M2I_Byrack_Enable_IMM25_14 : 24|2@1+ (1,0) [0|3] ""  IMM
 SG_ M2I_Byrack_ReVeEnable_IMM25_14 : 26|2@1+ (1,0) [0|3] ""  IMM
 SG_ Reserved_14 : 28|4@1+ (1,0) [0|15] ""  IMM
 SG_ M2I_Byrack_IsPostTm_IMM25_14 : 32|8@1+ (0.01,0) [0|2.55] "s"  IMM
 SG_ M2I_Byrack_SysABStTm_IMM25_14 : 40|16@1+ (0.01,0) [0|655.35] "s"  IMM
 SG_ Reserved_14 : 56|8@1+ (1,0) [0|255] ""  IMM

BO_ 2332113311 M2I_Byrack_SUMDATA25__15: 8 MBMU
 SG_ CRC_M2I_Byrack_IMM25_15 : 0|8@1+ (1,0) [0|255] ""  IMM
 SG_ M2I_Byrack_HVS_IMM25_15 : 8|16@1+ (0.1,0) [0|6553.5] "v"  IMM
 SG_ M2I_Byrack_Enable_IMM25_15 : 24|2@1+ (1,0) [0|3] ""  IMM
 SG_ M2I_Byrack_ReVeEnable_IMM25_15 : 26|2@1+ (1,0) [0|3] ""  IMM
 SG_ Reserved_15 : 28|4@1+ (1,0) [0|15] ""  IMM
 SG_ M2I_Byrack_IsPostTm_IMM25_15 : 32|8@1+ (0.01,0) [0|2.55] "s"  IMM
 SG_ M2I_Byrack_SysABStTm_IMM25_15 : 40|16@1+ (0.01,0) [0|655.35] "s"  IMM
 SG_ Reserved_15 : 56|8@1+ (1,0) [0|255] ""  IMM

BO_ 2332113312 M2I_Byrack_SUMDATA25__16: 8 MBMU
 SG_ CRC_M2I_Byrack_IMM25_16 : 0|8@1+ (1,0) [0|255] ""  IMM
 SG_ M2I_Byrack_HVS_IMM25_16 : 8|16@1+ (0.1,0) [0|6553.5] "v"  IMM
 SG_ M2I_Byrack_Enable_IMM25_16 : 24|2@1+ (1,0) [0|3] ""  IMM
 SG_ M2I_Byrack_ReVeEnable_IMM25_16 : 26|2@1+ (1,0) [0|3] ""  IMM
 SG_ Reserved_16 : 28|4@1+ (1,0) [0|15] ""  IMM
 SG_ M2I_Byrack_IsPostTm_IMM25_16 : 32|8@1+ (0.01,0) [0|2.55] "s"  IMM
 SG_ M2I_Byrack_SysABStTm_IMM25_16 : 40|16@1+ (0.01,0) [0|655.35] "s"  IMM
 SG_ Reserved_16 : 56|8@1+ (1,0) [0|255] ""  IMM

BO_ 2332113313 M2I_Byrack_SUMDATA25__17: 8 MBMU
 SG_ CRC_M2I_Byrack_IMM25_17 : 0|8@1+ (1,0) [0|255] ""  IMM
 SG_ M2I_Byrack_HVS_IMM25_17 : 8|16@1+ (0.1,0) [0|6553.5] "v"  IMM
 SG_ M2I_Byrack_Enable_IMM25_17 : 24|2@1+ (1,0) [0|3] ""  IMM
 SG_ M2I_Byrack_ReVeEnable_IMM25_17 : 26|2@1+ (1,0) [0|3] ""  IMM
 SG_ Reserved_17 : 28|4@1+ (1,0) [0|15] ""  IMM
 SG_ M2I_Byrack_IsPostTm_IMM25_17 : 32|8@1+ (0.01,0) [0|2.55] "s"  IMM
 SG_ M2I_Byrack_SysABStTm_IMM25_17 : 40|16@1+ (0.01,0) [0|655.35] "s"  IMM
 SG_ Reserved_17 : 56|8@1+ (1,0) [0|255] ""  IMM

BO_ 2332113314 M2I_Byrack_SUMDATA25__18: 8 MBMU
 SG_ CRC_M2I_Byrack_IMM25_18 : 0|8@1+ (1,0) [0|255] ""  IMM
 SG_ M2I_Byrack_HVS_IMM25_18 : 8|16@1+ (0.1,0) [0|6553.5] "v"  IMM
 SG_ M2I_Byrack_Enable_IMM25_18 : 24|2@1+ (1,0) [0|3] ""  IMM
 SG_ M2I_Byrack_ReVeEnable_IMM25_18 : 26|2@1+ (1,0) [0|3] ""  IMM
 SG_ Reserved_18 : 28|4@1+ (1,0) [0|15] ""  IMM
 SG_ M2I_Byrack_IsPostTm_IMM25_18 : 32|8@1+ (0.01,0) [0|2.55] "s"  IMM
 SG_ M2I_Byrack_SysABStTm_IMM25_18 : 40|16@1+ (0.01,0) [0|655.35] "s"  IMM
 SG_ Reserved_18 : 56|8@1+ (1,0) [0|255] ""  IMM

BO_ 2332113315 M2I_Byrack_SUMDATA25__19: 8 MBMU
 SG_ CRC_M2I_Byrack_IMM25_19 : 0|8@1+ (1,0) [0|255] ""  IMM
 SG_ M2I_Byrack_HVS_IMM25_19 : 8|16@1+ (0.1,0) [0|6553.5] "v"  IMM
 SG_ M2I_Byrack_Enable_IMM25_19 : 24|2@1+ (1,0) [0|3] ""  IMM
 SG_ M2I_Byrack_ReVeEnable_IMM25_19 : 26|2@1+ (1,0) [0|3] ""  IMM
 SG_ Reserved_19 : 28|4@1+ (1,0) [0|15] ""  IMM
 SG_ M2I_Byrack_IsPostTm_IMM25_19 : 32|8@1+ (0.01,0) [0|2.55] "s"  IMM
 SG_ M2I_Byrack_SysABStTm_IMM25_19 : 40|16@1+ (0.01,0) [0|655.35] "s"  IMM
 SG_ Reserved_19 : 56|8@1+ (1,0) [0|255] ""  IMM

BO_ 2332113316 M2I_Byrack_SUMDATA25__20: 8 MBMU
 SG_ CRC_M2I_Byrack_IMM25_20 : 0|8@1+ (1,0) [0|255] ""  IMM
 SG_ M2I_Byrack_HVS_IMM25_20 : 8|16@1+ (0.1,0) [0|6553.5] "v"  IMM
 SG_ M2I_Byrack_Enable_IMM25_20 : 24|2@1+ (1,0) [0|3] ""  IMM
 SG_ M2I_Byrack_ReVeEnable_IMM25_20 : 26|2@1+ (1,0) [0|3] ""  IMM
 SG_ Reserved_20 : 28|4@1+ (1,0) [0|15] ""  IMM
 SG_ M2I_Byrack_IsPostTm_IMM25_20 : 32|8@1+ (0.01,0) [0|2.55] "s"  IMM
 SG_ M2I_Byrack_SysABStTm_IMM25_20 : 40|16@1+ (0.01,0) [0|655.35] "s"  IMM
 SG_ Reserved_20 : 56|8@1+ (1,0) [0|255] ""  IMM

BO_ 2332113317 M2I_Byrack_SUMDATA25__21: 8 MBMU
 SG_ CRC_M2I_Byrack_IMM25_21 : 0|8@1+ (1,0) [0|255] ""  IMM
 SG_ M2I_Byrack_HVS_IMM25_21 : 8|16@1+ (0.1,0) [0|6553.5] "v"  IMM
 SG_ M2I_Byrack_Enable_IMM25_21 : 24|2@1+ (1,0) [0|3] ""  IMM
 SG_ M2I_Byrack_ReVeEnable_IMM25_21 : 26|2@1+ (1,0) [0|3] ""  IMM
 SG_ Reserved_21 : 28|4@1+ (1,0) [0|15] ""  IMM
 SG_ M2I_Byrack_IsPostTm_IMM25_21 : 32|8@1+ (0.01,0) [0|2.55] "s"  IMM
 SG_ M2I_Byrack_SysABStTm_IMM25_21 : 40|16@1+ (0.01,0) [0|655.35] "s"  IMM
 SG_ Reserved_21 : 56|8@1+ (1,0) [0|255] ""  IMM

BO_ 2332113318 M2I_Byrack_SUMDATA25__22: 8 MBMU
 SG_ CRC_M2I_Byrack_IMM25_22 : 0|8@1+ (1,0) [0|255] ""  IMM
 SG_ M2I_Byrack_HVS_IMM25_22 : 8|16@1+ (0.1,0) [0|6553.5] "v"  IMM
 SG_ M2I_Byrack_Enable_IMM25_22 : 24|2@1+ (1,0) [0|3] ""  IMM
 SG_ M2I_Byrack_ReVeEnable_IMM25_22 : 26|2@1+ (1,0) [0|3] ""  IMM
 SG_ Reserved_22 : 28|4@1+ (1,0) [0|15] ""  IMM
 SG_ M2I_Byrack_IsPostTm_IMM25_22 : 32|8@1+ (0.01,0) [0|2.55] "s"  IMM
 SG_ M2I_Byrack_SysABStTm_IMM25_22 : 40|16@1+ (0.01,0) [0|655.35] "s"  IMM
 SG_ Reserved_22 : 56|8@1+ (1,0) [0|255] ""  IMM

BO_ 2332113319 M2I_Byrack_SUMDATA25__23: 8 MBMU
 SG_ CRC_M2I_Byrack_IMM25_23 : 0|8@1+ (1,0) [0|255] ""  IMM
 SG_ M2I_Byrack_HVS_IMM25_23 : 8|16@1+ (0.1,0) [0|6553.5] "v"  IMM
 SG_ M2I_Byrack_Enable_IMM25_23 : 24|2@1+ (1,0) [0|3] ""  IMM
 SG_ M2I_Byrack_ReVeEnable_IMM25_23 : 26|2@1+ (1,0) [0|3] ""  IMM
 SG_ Reserved_23 : 28|4@1+ (1,0) [0|15] ""  IMM
 SG_ M2I_Byrack_IsPostTm_IMM25_23 : 32|8@1+ (0.01,0) [0|2.55] "s"  IMM
 SG_ M2I_Byrack_SysABStTm_IMM25_23 : 40|16@1+ (0.01,0) [0|655.35] "s"  IMM
 SG_ Reserved_23 : 56|8@1+ (1,0) [0|255] ""  IMM

BO_ 2332113320 M2I_Byrack_SUMDATA25__24: 8 MBMU
 SG_ CRC_M2I_Byrack_IMM25_24 : 0|8@1+ (1,0) [0|255] ""  IMM
 SG_ M2I_Byrack_HVS_IMM25_24 : 8|16@1+ (0.1,0) [0|6553.5] "v"  IMM
 SG_ M2I_Byrack_Enable_IMM25_24 : 24|2@1+ (1,0) [0|3] ""  IMM
 SG_ M2I_Byrack_ReVeEnable_IMM25_24 : 26|2@1+ (1,0) [0|3] ""  IMM
 SG_ Reserved_24 : 28|4@1+ (1,0) [0|15] ""  IMM
 SG_ M2I_Byrack_IsPostTm_IMM25_24 : 32|8@1+ (0.01,0) [0|2.55] "s"  IMM
 SG_ M2I_Byrack_SysABStTm_IMM25_24 : 40|16@1+ (0.01,0) [0|655.35] "s"  IMM
 SG_ Reserved_24 : 56|8@1+ (1,0) [0|255] ""  IMM

BO_ 2332113321 M2I_Byrack_SUMDATA25__25: 8 MBMU
 SG_ CRC_M2I_Byrack_IMM25_25 : 0|8@1+ (1,0) [0|255] ""  IMM
 SG_ M2I_Byrack_HVS_IMM25_25 : 8|16@1+ (0.1,0) [0|6553.5] "v"  IMM
 SG_ M2I_Byrack_Enable_IMM25_25 : 24|2@1+ (1,0) [0|3] ""  IMM
 SG_ M2I_Byrack_ReVeEnable_IMM25_25 : 26|2@1+ (1,0) [0|3] ""  IMM
 SG_ Reserved_25 : 28|4@1+ (1,0) [0|15] ""  IMM
 SG_ M2I_Byrack_IsPostTm_IMM25_25 : 32|8@1+ (0.01,0) [0|2.55] "s"  IMM
 SG_ M2I_Byrack_SysABStTm_IMM25_25 : 40|16@1+ (0.01,0) [0|655.35] "s"  IMM
 SG_ Reserved_25 : 56|8@1+ (1,0) [0|255] ""  IMM

BO_ 2332113322 M2I_Byrack_SUMDATA25__26: 8 MBMU
 SG_ CRC_M2I_Byrack_IMM25_26 : 0|8@1+ (1,0) [0|255] ""  IMM
 SG_ M2I_Byrack_HVS_IMM25_26 : 8|16@1+ (0.1,0) [0|6553.5] "v"  IMM
 SG_ M2I_Byrack_Enable_IMM25_26 : 24|2@1+ (1,0) [0|3] ""  IMM
 SG_ M2I_Byrack_ReVeEnable_IMM25_26 : 26|2@1+ (1,0) [0|3] ""  IMM
 SG_ Reserved_26 : 28|4@1+ (1,0) [0|15] ""  IMM
 SG_ M2I_Byrack_IsPostTm_IMM25_26 : 32|8@1+ (0.01,0) [0|2.55] "s"  IMM
 SG_ M2I_Byrack_SysABStTm_IMM25_26 : 40|16@1+ (0.01,0) [0|655.35] "s"  IMM
 SG_ Reserved_26 : 56|8@1+ (1,0) [0|255] ""  IMM

BO_ 2332113323 M2I_Byrack_SUMDATA25__27: 8 MBMU
 SG_ CRC_M2I_Byrack_IMM25_27 : 0|8@1+ (1,0) [0|255] ""  IMM
 SG_ M2I_Byrack_HVS_IMM25_27 : 8|16@1+ (0.1,0) [0|6553.5] "v"  IMM
 SG_ M2I_Byrack_Enable_IMM25_27 : 24|2@1+ (1,0) [0|3] ""  IMM
 SG_ M2I_Byrack_ReVeEnable_IMM25_27 : 26|2@1+ (1,0) [0|3] ""  IMM
 SG_ Reserved_27 : 28|4@1+ (1,0) [0|15] ""  IMM
 SG_ M2I_Byrack_IsPostTm_IMM25_27 : 32|8@1+ (0.01,0) [0|2.55] "s"  IMM
 SG_ M2I_Byrack_SysABStTm_IMM25_27 : 40|16@1+ (0.01,0) [0|655.35] "s"  IMM
 SG_ Reserved_27 : 56|8@1+ (1,0) [0|255] ""  IMM

BO_ 2332113324 M2I_Byrack_SUMDATA25__28: 8 MBMU
 SG_ CRC_M2I_Byrack_IMM25_28 : 0|8@1+ (1,0) [0|255] ""  IMM
 SG_ M2I_Byrack_HVS_IMM25_28 : 8|16@1+ (0.1,0) [0|6553.5] "v"  IMM
 SG_ M2I_Byrack_Enable_IMM25_28 : 24|2@1+ (1,0) [0|3] ""  IMM
 SG_ M2I_Byrack_ReVeEnable_IMM25_28 : 26|2@1+ (1,0) [0|3] ""  IMM
 SG_ Reserved_28 : 28|4@1+ (1,0) [0|15] ""  IMM
 SG_ M2I_Byrack_IsPostTm_IMM25_28 : 32|8@1+ (0.01,0) [0|2.55] "s"  IMM
 SG_ M2I_Byrack_SysABStTm_IMM25_28 : 40|16@1+ (0.01,0) [0|655.35] "s"  IMM
 SG_ Reserved_28 : 56|8@1+ (1,0) [0|255] ""  IMM

BO_ 2332113325 M2I_Byrack_SUMDATA25__29: 8 MBMU
 SG_ CRC_M2I_Byrack_IMM25_29 : 0|8@1+ (1,0) [0|255] ""  IMM
 SG_ M2I_Byrack_HVS_IMM25_29 : 8|16@1+ (0.1,0) [0|6553.5] "v"  IMM
 SG_ M2I_Byrack_Enable_IMM25_29 : 24|2@1+ (1,0) [0|3] ""  IMM
 SG_ M2I_Byrack_ReVeEnable_IMM25_29 : 26|2@1+ (1,0) [0|3] ""  IMM
 SG_ Reserved_29 : 28|4@1+ (1,0) [0|15] ""  IMM
 SG_ M2I_Byrack_IsPostTm_IMM25_29 : 32|8@1+ (0.01,0) [0|2.55] "s"  IMM
 SG_ M2I_Byrack_SysABStTm_IMM25_29 : 40|16@1+ (0.01,0) [0|655.35] "s"  IMM
 SG_ Reserved_29 : 56|8@1+ (1,0) [0|255] ""  IMM

BO_ 2332113326 M2I_Byrack_SUMDATA25__30: 8 MBMU
 SG_ CRC_M2I_Byrack_IMM25_30 : 0|8@1+ (1,0) [0|255] ""  IMM
 SG_ M2I_Byrack_HVS_IMM25_30 : 8|16@1+ (0.1,0) [0|6553.5] "v"  IMM
 SG_ M2I_Byrack_Enable_IMM25_30 : 24|2@1+ (1,0) [0|3] ""  IMM
 SG_ M2I_Byrack_ReVeEnable_IMM25_30 : 26|2@1+ (1,0) [0|3] ""  IMM
 SG_ Reserved_30 : 28|4@1+ (1,0) [0|15] ""  IMM
 SG_ M2I_Byrack_IsPostTm_IMM25_30 : 32|8@1+ (0.01,0) [0|2.55] "s"  IMM
 SG_ M2I_Byrack_SysABStTm_IMM25_30 : 40|16@1+ (0.01,0) [0|655.35] "s"  IMM
 SG_ Reserved_30 : 56|8@1+ (1,0) [0|255] ""  IMM

BO_ 2332113327 M2I_Byrack_SUMDATA25__31: 8 MBMU
 SG_ CRC_M2I_Byrack_IMM25_31 : 0|8@1+ (1,0) [0|255] ""  IMM
 SG_ M2I_Byrack_HVS_IMM25_31 : 8|16@1+ (0.1,0) [0|6553.5] "v"  IMM
 SG_ M2I_Byrack_Enable_IMM25_31 : 24|2@1+ (1,0) [0|3] ""  IMM
 SG_ M2I_Byrack_ReVeEnable_IMM25_31 : 26|2@1+ (1,0) [0|3] ""  IMM
 SG_ Reserved_31 : 28|4@1+ (1,0) [0|15] ""  IMM
 SG_ M2I_Byrack_IsPostTm_IMM25_31 : 32|8@1+ (0.01,0) [0|2.55] "s"  IMM
 SG_ M2I_Byrack_SysABStTm_IMM25_31 : 40|16@1+ (0.01,0) [0|655.35] "s"  IMM
 SG_ Reserved_31 : 56|8@1+ (1,0) [0|255] ""  IMM

BO_ 2332113553 M2I_Byrack_SUMDATA26__01: 8 MBMU
 SG_ CRC_M2I_Byrack_IMM26_01 : 0|8@1+ (1,0) [0|255] ""  IMM
 SG_ M2I_Byrack_HVS_IMM26_01 : 8|16@1+ (0.1,0) [0|6553.5] "v"  IMM
 SG_ M2I_Byrack_Enable_IMM26_01 : 24|2@1+ (1,0) [0|3] ""  IMM
 SG_ M2I_Byrack_ReVeEnable_IMM26_01 : 26|2@1+ (1,0) [0|3] ""  IMM
 SG_ Reserved_01 : 28|4@1+ (1,0) [0|15] ""  IMM
 SG_ M2I_Byrack_IsPostTm_IMM26_01 : 32|8@1+ (0.01,0) [0|2.55] "s"  IMM
 SG_ M2I_Byrack_SysABStTm_IMM26_01 : 40|16@1+ (0.01,0) [0|655.35] "s"  IMM
 SG_ Reserved_01 : 56|8@1+ (1,0) [0|255] ""  IMM

BO_ 2332113554 M2I_Byrack_SUMDATA26__02: 8 MBMU
 SG_ CRC_M2I_Byrack_IMM26_02 : 0|8@1+ (1,0) [0|255] ""  IMM
 SG_ M2I_Byrack_HVS_IMM26_02 : 8|16@1+ (0.1,0) [0|6553.5] "v"  IMM
 SG_ M2I_Byrack_Enable_IMM26_02 : 24|2@1+ (1,0) [0|3] ""  IMM
 SG_ M2I_Byrack_ReVeEnable_IMM26_02 : 26|2@1+ (1,0) [0|3] ""  IMM
 SG_ Reserved_02 : 28|4@1+ (1,0) [0|15] ""  IMM
 SG_ M2I_Byrack_IsPostTm_IMM26_02 : 32|8@1+ (0.01,0) [0|2.55] "s"  IMM
 SG_ M2I_Byrack_SysABStTm_IMM26_02 : 40|16@1+ (0.01,0) [0|655.35] "s"  IMM
 SG_ Reserved_02 : 56|8@1+ (1,0) [0|255] ""  IMM

BO_ 2332113555 M2I_Byrack_SUMDATA26__03: 8 MBMU
 SG_ CRC_M2I_Byrack_IMM26_03 : 0|8@1+ (1,0) [0|255] ""  IMM
 SG_ M2I_Byrack_HVS_IMM26_03 : 8|16@1+ (0.1,0) [0|6553.5] "v"  IMM
 SG_ M2I_Byrack_Enable_IMM26_03 : 24|2@1+ (1,0) [0|3] ""  IMM
 SG_ M2I_Byrack_ReVeEnable_IMM26_03 : 26|2@1+ (1,0) [0|3] ""  IMM
 SG_ Reserved_03 : 28|4@1+ (1,0) [0|15] ""  IMM
 SG_ M2I_Byrack_IsPostTm_IMM26_03 : 32|8@1+ (0.01,0) [0|2.55] "s"  IMM
 SG_ M2I_Byrack_SysABStTm_IMM26_03 : 40|16@1+ (0.01,0) [0|655.35] "s"  IMM
 SG_ Reserved_03 : 56|8@1+ (1,0) [0|255] ""  IMM

BO_ 2332113556 M2I_Byrack_SUMDATA26__04: 8 MBMU
 SG_ CRC_M2I_Byrack_IMM26_04 : 0|8@1+ (1,0) [0|255] ""  IMM
 SG_ M2I_Byrack_HVS_IMM26_04 : 8|16@1+ (0.1,0) [0|6553.5] "v"  IMM
 SG_ M2I_Byrack_Enable_IMM26_04 : 24|2@1+ (1,0) [0|3] ""  IMM
 SG_ M2I_Byrack_ReVeEnable_IMM26_04 : 26|2@1+ (1,0) [0|3] ""  IMM
 SG_ Reserved_04 : 28|4@1+ (1,0) [0|15] ""  IMM
 SG_ M2I_Byrack_IsPostTm_IMM26_04 : 32|8@1+ (0.01,0) [0|2.55] "s"  IMM
 SG_ M2I_Byrack_SysABStTm_IMM26_04 : 40|16@1+ (0.01,0) [0|655.35] "s"  IMM
 SG_ Reserved_04 : 56|8@1+ (1,0) [0|255] ""  IMM

BO_ 2332113557 M2I_Byrack_SUMDATA26__05: 8 MBMU
 SG_ CRC_M2I_Byrack_IMM26_05 : 0|8@1+ (1,0) [0|255] ""  IMM
 SG_ M2I_Byrack_HVS_IMM26_05 : 8|16@1+ (0.1,0) [0|6553.5] "v"  IMM
 SG_ M2I_Byrack_Enable_IMM26_05 : 24|2@1+ (1,0) [0|3] ""  IMM
 SG_ M2I_Byrack_ReVeEnable_IMM26_05 : 26|2@1+ (1,0) [0|3] ""  IMM
 SG_ Reserved_05 : 28|4@1+ (1,0) [0|15] ""  IMM
 SG_ M2I_Byrack_IsPostTm_IMM26_05 : 32|8@1+ (0.01,0) [0|2.55] "s"  IMM
 SG_ M2I_Byrack_SysABStTm_IMM26_05 : 40|16@1+ (0.01,0) [0|655.35] "s"  IMM
 SG_ Reserved_05 : 56|8@1+ (1,0) [0|255] ""  IMM

BO_ 2332113558 M2I_Byrack_SUMDATA26__06: 8 MBMU
 SG_ CRC_M2I_Byrack_IMM26_06 : 0|8@1+ (1,0) [0|255] ""  IMM
 SG_ M2I_Byrack_HVS_IMM26_06 : 8|16@1+ (0.1,0) [0|6553.5] "v"  IMM
 SG_ M2I_Byrack_Enable_IMM26_06 : 24|2@1+ (1,0) [0|3] ""  IMM
 SG_ M2I_Byrack_ReVeEnable_IMM26_06 : 26|2@1+ (1,0) [0|3] ""  IMM
 SG_ Reserved_06 : 28|4@1+ (1,0) [0|15] ""  IMM
 SG_ M2I_Byrack_IsPostTm_IMM26_06 : 32|8@1+ (0.01,0) [0|2.55] "s"  IMM
 SG_ M2I_Byrack_SysABStTm_IMM26_06 : 40|16@1+ (0.01,0) [0|655.35] "s"  IMM
 SG_ Reserved_06 : 56|8@1+ (1,0) [0|255] ""  IMM

BO_ 2332113559 M2I_Byrack_SUMDATA26__07: 8 MBMU
 SG_ CRC_M2I_Byrack_IMM26_07 : 0|8@1+ (1,0) [0|255] ""  IMM
 SG_ M2I_Byrack_HVS_IMM26_07 : 8|16@1+ (0.1,0) [0|6553.5] "v"  IMM
 SG_ M2I_Byrack_Enable_IMM26_07 : 24|2@1+ (1,0) [0|3] ""  IMM
 SG_ M2I_Byrack_ReVeEnable_IMM26_07 : 26|2@1+ (1,0) [0|3] ""  IMM
 SG_ Reserved_07 : 28|4@1+ (1,0) [0|15] ""  IMM
 SG_ M2I_Byrack_IsPostTm_IMM26_07 : 32|8@1+ (0.01,0) [0|2.55] "s"  IMM
 SG_ M2I_Byrack_SysABStTm_IMM26_07 : 40|16@1+ (0.01,0) [0|655.35] "s"  IMM
 SG_ Reserved_07 : 56|8@1+ (1,0) [0|255] ""  IMM

BO_ 2332113560 M2I_Byrack_SUMDATA26__08: 8 MBMU
 SG_ CRC_M2I_Byrack_IMM26_08 : 0|8@1+ (1,0) [0|255] ""  IMM
 SG_ M2I_Byrack_HVS_IMM26_08 : 8|16@1+ (0.1,0) [0|6553.5] "v"  IMM
 SG_ M2I_Byrack_Enable_IMM26_08 : 24|2@1+ (1,0) [0|3] ""  IMM
 SG_ M2I_Byrack_ReVeEnable_IMM26_08 : 26|2@1+ (1,0) [0|3] ""  IMM
 SG_ Reserved_08 : 28|4@1+ (1,0) [0|15] ""  IMM
 SG_ M2I_Byrack_IsPostTm_IMM26_08 : 32|8@1+ (0.01,0) [0|2.55] "s"  IMM
 SG_ M2I_Byrack_SysABStTm_IMM26_08 : 40|16@1+ (0.01,0) [0|655.35] "s"  IMM
 SG_ Reserved_08 : 56|8@1+ (1,0) [0|255] ""  IMM

BO_ 2332113561 M2I_Byrack_SUMDATA26__09: 8 MBMU
 SG_ CRC_M2I_Byrack_IMM26_09 : 0|8@1+ (1,0) [0|255] ""  IMM
 SG_ M2I_Byrack_HVS_IMM26_09 : 8|16@1+ (0.1,0) [0|6553.5] "v"  IMM
 SG_ M2I_Byrack_Enable_IMM26_09 : 24|2@1+ (1,0) [0|3] ""  IMM
 SG_ M2I_Byrack_ReVeEnable_IMM26_09 : 26|2@1+ (1,0) [0|3] ""  IMM
 SG_ Reserved_09 : 28|4@1+ (1,0) [0|15] ""  IMM
 SG_ M2I_Byrack_IsPostTm_IMM26_09 : 32|8@1+ (0.01,0) [0|2.55] "s"  IMM
 SG_ M2I_Byrack_SysABStTm_IMM26_09 : 40|16@1+ (0.01,0) [0|655.35] "s"  IMM
 SG_ Reserved_09 : 56|8@1+ (1,0) [0|255] ""  IMM

BO_ 2332113562 M2I_Byrack_SUMDATA26__10: 8 MBMU
 SG_ CRC_M2I_Byrack_IMM26_10 : 0|8@1+ (1,0) [0|255] ""  IMM
 SG_ M2I_Byrack_HVS_IMM26_10 : 8|16@1+ (0.1,0) [0|6553.5] "v"  IMM
 SG_ M2I_Byrack_Enable_IMM26_10 : 24|2@1+ (1,0) [0|3] ""  IMM
 SG_ M2I_Byrack_ReVeEnable_IMM26_10 : 26|2@1+ (1,0) [0|3] ""  IMM
 SG_ Reserved_10 : 28|4@1+ (1,0) [0|15] ""  IMM
 SG_ M2I_Byrack_IsPostTm_IMM26_10 : 32|8@1+ (0.01,0) [0|2.55] "s"  IMM
 SG_ M2I_Byrack_SysABStTm_IMM26_10 : 40|16@1+ (0.01,0) [0|655.35] "s"  IMM
 SG_ Reserved_10 : 56|8@1+ (1,0) [0|255] ""  IMM

BO_ 2332113563 M2I_Byrack_SUMDATA26__11: 8 MBMU
 SG_ CRC_M2I_Byrack_IMM26_11 : 0|8@1+ (1,0) [0|255] ""  IMM
 SG_ M2I_Byrack_HVS_IMM26_11 : 8|16@1+ (0.1,0) [0|6553.5] "v"  IMM
 SG_ M2I_Byrack_Enable_IMM26_11 : 24|2@1+ (1,0) [0|3] ""  IMM
 SG_ M2I_Byrack_ReVeEnable_IMM26_11 : 26|2@1+ (1,0) [0|3] ""  IMM
 SG_ Reserved_11 : 28|4@1+ (1,0) [0|15] ""  IMM
 SG_ M2I_Byrack_IsPostTm_IMM26_11 : 32|8@1+ (0.01,0) [0|2.55] "s"  IMM
 SG_ M2I_Byrack_SysABStTm_IMM26_11 : 40|16@1+ (0.01,0) [0|655.35] "s"  IMM
 SG_ Reserved_11 : 56|8@1+ (1,0) [0|255] ""  IMM

BO_ 2332113564 M2I_Byrack_SUMDATA26__12: 8 MBMU
 SG_ CRC_M2I_Byrack_IMM26_12 : 0|8@1+ (1,0) [0|255] ""  IMM
 SG_ M2I_Byrack_HVS_IMM26_12 : 8|16@1+ (0.1,0) [0|6553.5] "v"  IMM
 SG_ M2I_Byrack_Enable_IMM26_12 : 24|2@1+ (1,0) [0|3] ""  IMM
 SG_ M2I_Byrack_ReVeEnable_IMM26_12 : 26|2@1+ (1,0) [0|3] ""  IMM
 SG_ Reserved_12 : 28|4@1+ (1,0) [0|15] ""  IMM
 SG_ M2I_Byrack_IsPostTm_IMM26_12 : 32|8@1+ (0.01,0) [0|2.55] "s"  IMM
 SG_ M2I_Byrack_SysABStTm_IMM26_12 : 40|16@1+ (0.01,0) [0|655.35] "s"  IMM
 SG_ Reserved_12 : 56|8@1+ (1,0) [0|255] ""  IMM

BO_ 2332113565 M2I_Byrack_SUMDATA26__13: 8 MBMU
 SG_ CRC_M2I_Byrack_IMM26_13 : 0|8@1+ (1,0) [0|255] ""  IMM
 SG_ M2I_Byrack_HVS_IMM26_13 : 8|16@1+ (0.1,0) [0|6553.5] "v"  IMM
 SG_ M2I_Byrack_Enable_IMM26_13 : 24|2@1+ (1,0) [0|3] ""  IMM
 SG_ M2I_Byrack_ReVeEnable_IMM26_13 : 26|2@1+ (1,0) [0|3] ""  IMM
 SG_ Reserved_13 : 28|4@1+ (1,0) [0|15] ""  IMM
 SG_ M2I_Byrack_IsPostTm_IMM26_13 : 32|8@1+ (0.01,0) [0|2.55] "s"  IMM
 SG_ M2I_Byrack_SysABStTm_IMM26_13 : 40|16@1+ (0.01,0) [0|655.35] "s"  IMM
 SG_ Reserved_13 : 56|8@1+ (1,0) [0|255] ""  IMM

BO_ 2332113566 M2I_Byrack_SUMDATA26__14: 8 MBMU
 SG_ CRC_M2I_Byrack_IMM26_14 : 0|8@1+ (1,0) [0|255] ""  IMM
 SG_ M2I_Byrack_HVS_IMM26_14 : 8|16@1+ (0.1,0) [0|6553.5] "v"  IMM
 SG_ M2I_Byrack_Enable_IMM26_14 : 24|2@1+ (1,0) [0|3] ""  IMM
 SG_ M2I_Byrack_ReVeEnable_IMM26_14 : 26|2@1+ (1,0) [0|3] ""  IMM
 SG_ Reserved_14 : 28|4@1+ (1,0) [0|15] ""  IMM
 SG_ M2I_Byrack_IsPostTm_IMM26_14 : 32|8@1+ (0.01,0) [0|2.55] "s"  IMM
 SG_ M2I_Byrack_SysABStTm_IMM26_14 : 40|16@1+ (0.01,0) [0|655.35] "s"  IMM
 SG_ Reserved_14 : 56|8@1+ (1,0) [0|255] ""  IMM

BO_ 2332113567 M2I_Byrack_SUMDATA26__15: 8 MBMU
 SG_ CRC_M2I_Byrack_IMM26_15 : 0|8@1+ (1,0) [0|255] ""  IMM
 SG_ M2I_Byrack_HVS_IMM26_15 : 8|16@1+ (0.1,0) [0|6553.5] "v"  IMM
 SG_ M2I_Byrack_Enable_IMM26_15 : 24|2@1+ (1,0) [0|3] ""  IMM
 SG_ M2I_Byrack_ReVeEnable_IMM26_15 : 26|2@1+ (1,0) [0|3] ""  IMM
 SG_ Reserved_15 : 28|4@1+ (1,0) [0|15] ""  IMM
 SG_ M2I_Byrack_IsPostTm_IMM26_15 : 32|8@1+ (0.01,0) [0|2.55] "s"  IMM
 SG_ M2I_Byrack_SysABStTm_IMM26_15 : 40|16@1+ (0.01,0) [0|655.35] "s"  IMM
 SG_ Reserved_15 : 56|8@1+ (1,0) [0|255] ""  IMM

BO_ 2332113568 M2I_Byrack_SUMDATA26__16: 8 MBMU
 SG_ CRC_M2I_Byrack_IMM26_16 : 0|8@1+ (1,0) [0|255] ""  IMM
 SG_ M2I_Byrack_HVS_IMM26_16 : 8|16@1+ (0.1,0) [0|6553.5] "v"  IMM
 SG_ M2I_Byrack_Enable_IMM26_16 : 24|2@1+ (1,0) [0|3] ""  IMM
 SG_ M2I_Byrack_ReVeEnable_IMM26_16 : 26|2@1+ (1,0) [0|3] ""  IMM
 SG_ Reserved_16 : 28|4@1+ (1,0) [0|15] ""  IMM
 SG_ M2I_Byrack_IsPostTm_IMM26_16 : 32|8@1+ (0.01,0) [0|2.55] "s"  IMM
 SG_ M2I_Byrack_SysABStTm_IMM26_16 : 40|16@1+ (0.01,0) [0|655.35] "s"  IMM
 SG_ Reserved_16 : 56|8@1+ (1,0) [0|255] ""  IMM

BO_ 2332113569 M2I_Byrack_SUMDATA26__17: 8 MBMU
 SG_ CRC_M2I_Byrack_IMM26_17 : 0|8@1+ (1,0) [0|255] ""  IMM
 SG_ M2I_Byrack_HVS_IMM26_17 : 8|16@1+ (0.1,0) [0|6553.5] "v"  IMM
 SG_ M2I_Byrack_Enable_IMM26_17 : 24|2@1+ (1,0) [0|3] ""  IMM
 SG_ M2I_Byrack_ReVeEnable_IMM26_17 : 26|2@1+ (1,0) [0|3] ""  IMM
 SG_ Reserved_17 : 28|4@1+ (1,0) [0|15] ""  IMM
 SG_ M2I_Byrack_IsPostTm_IMM26_17 : 32|8@1+ (0.01,0) [0|2.55] "s"  IMM
 SG_ M2I_Byrack_SysABStTm_IMM26_17 : 40|16@1+ (0.01,0) [0|655.35] "s"  IMM
 SG_ Reserved_17 : 56|8@1+ (1,0) [0|255] ""  IMM

BO_ 2332113570 M2I_Byrack_SUMDATA26__18: 8 MBMU
 SG_ CRC_M2I_Byrack_IMM26_18 : 0|8@1+ (1,0) [0|255] ""  IMM
 SG_ M2I_Byrack_HVS_IMM26_18 : 8|16@1+ (0.1,0) [0|6553.5] "v"  IMM
 SG_ M2I_Byrack_Enable_IMM26_18 : 24|2@1+ (1,0) [0|3] ""  IMM
 SG_ M2I_Byrack_ReVeEnable_IMM26_18 : 26|2@1+ (1,0) [0|3] ""  IMM
 SG_ Reserved_18 : 28|4@1+ (1,0) [0|15] ""  IMM
 SG_ M2I_Byrack_IsPostTm_IMM26_18 : 32|8@1+ (0.01,0) [0|2.55] "s"  IMM
 SG_ M2I_Byrack_SysABStTm_IMM26_18 : 40|16@1+ (0.01,0) [0|655.35] "s"  IMM
 SG_ Reserved_18 : 56|8@1+ (1,0) [0|255] ""  IMM

BO_ 2332113571 M2I_Byrack_SUMDATA26__19: 8 MBMU
 SG_ CRC_M2I_Byrack_IMM26_19 : 0|8@1+ (1,0) [0|255] ""  IMM
 SG_ M2I_Byrack_HVS_IMM26_19 : 8|16@1+ (0.1,0) [0|6553.5] "v"  IMM
 SG_ M2I_Byrack_Enable_IMM26_19 : 24|2@1+ (1,0) [0|3] ""  IMM
 SG_ M2I_Byrack_ReVeEnable_IMM26_19 : 26|2@1+ (1,0) [0|3] ""  IMM
 SG_ Reserved_19 : 28|4@1+ (1,0) [0|15] ""  IMM
 SG_ M2I_Byrack_IsPostTm_IMM26_19 : 32|8@1+ (0.01,0) [0|2.55] "s"  IMM
 SG_ M2I_Byrack_SysABStTm_IMM26_19 : 40|16@1+ (0.01,0) [0|655.35] "s"  IMM
 SG_ Reserved_19 : 56|8@1+ (1,0) [0|255] ""  IMM

BO_ 2332113572 M2I_Byrack_SUMDATA26__20: 8 MBMU
 SG_ CRC_M2I_Byrack_IMM26_20 : 0|8@1+ (1,0) [0|255] ""  IMM
 SG_ M2I_Byrack_HVS_IMM26_20 : 8|16@1+ (0.1,0) [0|6553.5] "v"  IMM
 SG_ M2I_Byrack_Enable_IMM26_20 : 24|2@1+ (1,0) [0|3] ""  IMM
 SG_ M2I_Byrack_ReVeEnable_IMM26_20 : 26|2@1+ (1,0) [0|3] ""  IMM
 SG_ Reserved_20 : 28|4@1+ (1,0) [0|15] ""  IMM
 SG_ M2I_Byrack_IsPostTm_IMM26_20 : 32|8@1+ (0.01,0) [0|2.55] "s"  IMM
 SG_ M2I_Byrack_SysABStTm_IMM26_20 : 40|16@1+ (0.01,0) [0|655.35] "s"  IMM
 SG_ Reserved_20 : 56|8@1+ (1,0) [0|255] ""  IMM

BO_ 2332113573 M2I_Byrack_SUMDATA26__21: 8 MBMU
 SG_ CRC_M2I_Byrack_IMM26_21 : 0|8@1+ (1,0) [0|255] ""  IMM
 SG_ M2I_Byrack_HVS_IMM26_21 : 8|16@1+ (0.1,0) [0|6553.5] "v"  IMM
 SG_ M2I_Byrack_Enable_IMM26_21 : 24|2@1+ (1,0) [0|3] ""  IMM
 SG_ M2I_Byrack_ReVeEnable_IMM26_21 : 26|2@1+ (1,0) [0|3] ""  IMM
 SG_ Reserved_21 : 28|4@1+ (1,0) [0|15] ""  IMM
 SG_ M2I_Byrack_IsPostTm_IMM26_21 : 32|8@1+ (0.01,0) [0|2.55] "s"  IMM
 SG_ M2I_Byrack_SysABStTm_IMM26_21 : 40|16@1+ (0.01,0) [0|655.35] "s"  IMM
 SG_ Reserved_21 : 56|8@1+ (1,0) [0|255] ""  IMM

BO_ 2332113574 M2I_Byrack_SUMDATA26__22: 8 MBMU
 SG_ CRC_M2I_Byrack_IMM26_22 : 0|8@1+ (1,0) [0|255] ""  IMM
 SG_ M2I_Byrack_HVS_IMM26_22 : 8|16@1+ (0.1,0) [0|6553.5] "v"  IMM
 SG_ M2I_Byrack_Enable_IMM26_22 : 24|2@1+ (1,0) [0|3] ""  IMM
 SG_ M2I_Byrack_ReVeEnable_IMM26_22 : 26|2@1+ (1,0) [0|3] ""  IMM
 SG_ Reserved_22 : 28|4@1+ (1,0) [0|15] ""  IMM
 SG_ M2I_Byrack_IsPostTm_IMM26_22 : 32|8@1+ (0.01,0) [0|2.55] "s"  IMM
 SG_ M2I_Byrack_SysABStTm_IMM26_22 : 40|16@1+ (0.01,0) [0|655.35] "s"  IMM
 SG_ Reserved_22 : 56|8@1+ (1,0) [0|255] ""  IMM

BO_ 2332113575 M2I_Byrack_SUMDATA26__23: 8 MBMU
 SG_ CRC_M2I_Byrack_IMM26_23 : 0|8@1+ (1,0) [0|255] ""  IMM
 SG_ M2I_Byrack_HVS_IMM26_23 : 8|16@1+ (0.1,0) [0|6553.5] "v"  IMM
 SG_ M2I_Byrack_Enable_IMM26_23 : 24|2@1+ (1,0) [0|3] ""  IMM
 SG_ M2I_Byrack_ReVeEnable_IMM26_23 : 26|2@1+ (1,0) [0|3] ""  IMM
 SG_ Reserved_23 : 28|4@1+ (1,0) [0|15] ""  IMM
 SG_ M2I_Byrack_IsPostTm_IMM26_23 : 32|8@1+ (0.01,0) [0|2.55] "s"  IMM
 SG_ M2I_Byrack_SysABStTm_IMM26_23 : 40|16@1+ (0.01,0) [0|655.35] "s"  IMM
 SG_ Reserved_23 : 56|8@1+ (1,0) [0|255] ""  IMM

BO_ 2332113576 M2I_Byrack_SUMDATA26__24: 8 MBMU
 SG_ CRC_M2I_Byrack_IMM26_24 : 0|8@1+ (1,0) [0|255] ""  IMM
 SG_ M2I_Byrack_HVS_IMM26_24 : 8|16@1+ (0.1,0) [0|6553.5] "v"  IMM
 SG_ M2I_Byrack_Enable_IMM26_24 : 24|2@1+ (1,0) [0|3] ""  IMM
 SG_ M2I_Byrack_ReVeEnable_IMM26_24 : 26|2@1+ (1,0) [0|3] ""  IMM
 SG_ Reserved_24 : 28|4@1+ (1,0) [0|15] ""  IMM
 SG_ M2I_Byrack_IsPostTm_IMM26_24 : 32|8@1+ (0.01,0) [0|2.55] "s"  IMM
 SG_ M2I_Byrack_SysABStTm_IMM26_24 : 40|16@1+ (0.01,0) [0|655.35] "s"  IMM
 SG_ Reserved_24 : 56|8@1+ (1,0) [0|255] ""  IMM

BO_ 2332113577 M2I_Byrack_SUMDATA26__25: 8 MBMU
 SG_ CRC_M2I_Byrack_IMM26_25 : 0|8@1+ (1,0) [0|255] ""  IMM
 SG_ M2I_Byrack_HVS_IMM26_25 : 8|16@1+ (0.1,0) [0|6553.5] "v"  IMM
 SG_ M2I_Byrack_Enable_IMM26_25 : 24|2@1+ (1,0) [0|3] ""  IMM
 SG_ M2I_Byrack_ReVeEnable_IMM26_25 : 26|2@1+ (1,0) [0|3] ""  IMM
 SG_ Reserved_25 : 28|4@1+ (1,0) [0|15] ""  IMM
 SG_ M2I_Byrack_IsPostTm_IMM26_25 : 32|8@1+ (0.01,0) [0|2.55] "s"  IMM
 SG_ M2I_Byrack_SysABStTm_IMM26_25 : 40|16@1+ (0.01,0) [0|655.35] "s"  IMM
 SG_ Reserved_25 : 56|8@1+ (1,0) [0|255] ""  IMM

BO_ 2332113578 M2I_Byrack_SUMDATA26__26: 8 MBMU
 SG_ CRC_M2I_Byrack_IMM26_26 : 0|8@1+ (1,0) [0|255] ""  IMM
 SG_ M2I_Byrack_HVS_IMM26_26 : 8|16@1+ (0.1,0) [0|6553.5] "v"  IMM
 SG_ M2I_Byrack_Enable_IMM26_26 : 24|2@1+ (1,0) [0|3] ""  IMM
 SG_ M2I_Byrack_ReVeEnable_IMM26_26 : 26|2@1+ (1,0) [0|3] ""  IMM
 SG_ Reserved_26 : 28|4@1+ (1,0) [0|15] ""  IMM
 SG_ M2I_Byrack_IsPostTm_IMM26_26 : 32|8@1+ (0.01,0) [0|2.55] "s"  IMM
 SG_ M2I_Byrack_SysABStTm_IMM26_26 : 40|16@1+ (0.01,0) [0|655.35] "s"  IMM
 SG_ Reserved_26 : 56|8@1+ (1,0) [0|255] ""  IMM

CM_ SG_ 2332112289 CRC_M2I_Byrack_IMM21_17 "CRC校验_IMM21";
CM_ SG_ 2332112289 M2I_Byrack_HVS_IMM21_17 "绝缘测量电压_IMM21";
CM_ SG_ 2332112289 M2I_Byrack_Enable_IMM21_17 "绝缘采样使能位_IMM21";
CM_ SG_ 2332112289 M2I_Byrack_ReVeEnable_IMM21_17 "读取软件版本使能位_IMM21";
CM_ SG_ 2332112289 Reserved_17 "预留预留";
CM_ SG_ 2332112289 M2I_Byrack_IsPostTm_IMM21_17 "绝缘采样时间_IMM21";
CM_ SG_ 2332112289 M2I_Byrack_SysABStTm_IMM21_17 "电压稳定时间_IMM21";
CM_ SG_ 2332112290 CRC_M2I_Byrack_IMM21_18 "CRC校验_IMM21";
CM_ SG_ 2332112290 M2I_Byrack_HVS_IMM21_18 "绝缘测量电压_IMM21";
CM_ SG_ 2332112290 M2I_Byrack_Enable_IMM21_18 "绝缘采样使能位_IMM21";
CM_ SG_ 2332112290 M2I_Byrack_ReVeEnable_IMM21_18 "读取软件版本使能位_IMM21";
CM_ SG_ 2332112290 Reserved_18 "预留预留";
CM_ SG_ 2332112290 M2I_Byrack_IsPostTm_IMM21_18 "绝缘采样时间_IMM21";
CM_ SG_ 2332112290 M2I_Byrack_SysABStTm_IMM21_18 "电压稳定时间_IMM21";
CM_ SG_ 2332112291 CRC_M2I_Byrack_IMM21_19 "CRC校验_IMM21";
CM_ SG_ 2332112291 M2I_Byrack_HVS_IMM21_19 "绝缘测量电压_IMM21";
CM_ SG_ 2332112291 M2I_Byrack_Enable_IMM21_19 "绝缘采样使能位_IMM21";
CM_ SG_ 2332112291 M2I_Byrack_ReVeEnable_IMM21_19 "读取软件版本使能位_IMM21";
CM_ SG_ 2332112291 Reserved_19 "预留预留";
CM_ SG_ 2332112291 M2I_Byrack_IsPostTm_IMM21_19 "绝缘采样时间_IMM21";
CM_ SG_ 2332112291 M2I_Byrack_SysABStTm_IMM21_19 "电压稳定时间_IMM21";
CM_ SG_ 2332112292 CRC_M2I_Byrack_IMM21_20 "CRC校验_IMM21";
CM_ SG_ 2332112292 M2I_Byrack_HVS_IMM21_20 "绝缘测量电压_IMM21";
CM_ SG_ 2332112292 M2I_Byrack_Enable_IMM21_20 "绝缘采样使能位_IMM21";
CM_ SG_ 2332112292 M2I_Byrack_ReVeEnable_IMM21_20 "读取软件版本使能位_IMM21";
CM_ SG_ 2332112292 Reserved_20 "预留预留";
CM_ SG_ 2332112292 M2I_Byrack_IsPostTm_IMM21_20 "绝缘采样时间_IMM21";
CM_ SG_ 2332112292 M2I_Byrack_SysABStTm_IMM21_20 "电压稳定时间_IMM21";
CM_ SG_ 2332112293 CRC_M2I_Byrack_IMM21_21 "CRC校验_IMM21";
CM_ SG_ 2332112293 M2I_Byrack_HVS_IMM21_21 "绝缘测量电压_IMM21";
CM_ SG_ 2332112293 M2I_Byrack_Enable_IMM21_21 "绝缘采样使能位_IMM21";
CM_ SG_ 2332112293 M2I_Byrack_ReVeEnable_IMM21_21 "读取软件版本使能位_IMM21";
CM_ SG_ 2332112293 Reserved_21 "预留预留";
CM_ SG_ 2332112293 M2I_Byrack_IsPostTm_IMM21_21 "绝缘采样时间_IMM21";
CM_ SG_ 2332112293 M2I_Byrack_SysABStTm_IMM21_21 "电压稳定时间_IMM21";
CM_ SG_ 2332112294 CRC_M2I_Byrack_IMM21_22 "CRC校验_IMM21";
CM_ SG_ 2332112294 M2I_Byrack_HVS_IMM21_22 "绝缘测量电压_IMM21";
CM_ SG_ 2332112294 M2I_Byrack_Enable_IMM21_22 "绝缘采样使能位_IMM21";
CM_ SG_ 2332112294 M2I_Byrack_ReVeEnable_IMM21_22 "读取软件版本使能位_IMM21";
CM_ SG_ 2332112294 Reserved_22 "预留预留";
CM_ SG_ 2332112294 M2I_Byrack_IsPostTm_IMM21_22 "绝缘采样时间_IMM21";
CM_ SG_ 2332112294 M2I_Byrack_SysABStTm_IMM21_22 "电压稳定时间_IMM21";
CM_ SG_ 2332112295 CRC_M2I_Byrack_IMM21_23 "CRC校验_IMM21";
CM_ SG_ 2332112295 M2I_Byrack_HVS_IMM21_23 "绝缘测量电压_IMM21";
CM_ SG_ 2332112295 M2I_Byrack_Enable_IMM21_23 "绝缘采样使能位_IMM21";
CM_ SG_ 2332112295 M2I_Byrack_ReVeEnable_IMM21_23 "读取软件版本使能位_IMM21";
CM_ SG_ 2332112295 Reserved_23 "预留预留";
CM_ SG_ 2332112295 M2I_Byrack_IsPostTm_IMM21_23 "绝缘采样时间_IMM21";
CM_ SG_ 2332112295 M2I_Byrack_SysABStTm_IMM21_23 "电压稳定时间_IMM21";
CM_ SG_ 2332112296 CRC_M2I_Byrack_IMM21_24 "CRC校验_IMM21";
CM_ SG_ 2332112296 M2I_Byrack_HVS_IMM21_24 "绝缘测量电压_IMM21";
CM_ SG_ 2332112296 M2I_Byrack_Enable_IMM21_24 "绝缘采样使能位_IMM21";
CM_ SG_ 2332112296 M2I_Byrack_ReVeEnable_IMM21_24 "读取软件版本使能位_IMM21";
CM_ SG_ 2332112296 Reserved_24 "预留预留";
CM_ SG_ 2332112296 M2I_Byrack_IsPostTm_IMM21_24 "绝缘采样时间_IMM21";
CM_ SG_ 2332112296 M2I_Byrack_SysABStTm_IMM21_24 "电压稳定时间_IMM21";
CM_ SG_ 2332112297 CRC_M2I_Byrack_IMM21_25 "CRC校验_IMM21";
CM_ SG_ 2332112297 M2I_Byrack_HVS_IMM21_25 "绝缘测量电压_IMM21";
CM_ SG_ 2332112297 M2I_Byrack_Enable_IMM21_25 "绝缘采样使能位_IMM21";
CM_ SG_ 2332112297 M2I_Byrack_ReVeEnable_IMM21_25 "读取软件版本使能位_IMM21";
CM_ SG_ 2332112297 Reserved_25 "预留预留";
CM_ SG_ 2332112297 M2I_Byrack_IsPostTm_IMM21_25 "绝缘采样时间_IMM21";
CM_ SG_ 2332112297 M2I_Byrack_SysABStTm_IMM21_25 "电压稳定时间_IMM21";
CM_ SG_ 2332112298 CRC_M2I_Byrack_IMM21_26 "CRC校验_IMM21";
CM_ SG_ 2332112298 M2I_Byrack_HVS_IMM21_26 "绝缘测量电压_IMM21";
CM_ SG_ 2332112298 M2I_Byrack_Enable_IMM21_26 "绝缘采样使能位_IMM21";
CM_ SG_ 2332112298 M2I_Byrack_ReVeEnable_IMM21_26 "读取软件版本使能位_IMM21";
CM_ SG_ 2332112298 Reserved_26 "预留预留";
CM_ SG_ 2332112298 M2I_Byrack_IsPostTm_IMM21_26 "绝缘采样时间_IMM21";
CM_ SG_ 2332112298 M2I_Byrack_SysABStTm_IMM21_26 "电压稳定时间_IMM21";
CM_ SG_ 2332112299 CRC_M2I_Byrack_IMM21_27 "CRC校验_IMM21";
CM_ SG_ 2332112299 M2I_Byrack_HVS_IMM21_27 "绝缘测量电压_IMM21";
CM_ SG_ 2332112299 M2I_Byrack_Enable_IMM21_27 "绝缘采样使能位_IMM21";
CM_ SG_ 2332112299 M2I_Byrack_ReVeEnable_IMM21_27 "读取软件版本使能位_IMM21";
CM_ SG_ 2332112299 Reserved_27 "预留预留";
CM_ SG_ 2332112299 M2I_Byrack_IsPostTm_IMM21_27 "绝缘采样时间_IMM21";
CM_ SG_ 2332112299 M2I_Byrack_SysABStTm_IMM21_27 "电压稳定时间_IMM21";
CM_ SG_ 2332112300 CRC_M2I_Byrack_IMM21_28 "CRC校验_IMM21";
CM_ SG_ 2332112300 M2I_Byrack_HVS_IMM21_28 "绝缘测量电压_IMM21";
CM_ SG_ 2332112300 M2I_Byrack_Enable_IMM21_28 "绝缘采样使能位_IMM21";
CM_ SG_ 2332112300 M2I_Byrack_ReVeEnable_IMM21_28 "读取软件版本使能位_IMM21";
CM_ SG_ 2332112300 Reserved_28 "预留预留";
CM_ SG_ 2332112300 M2I_Byrack_IsPostTm_IMM21_28 "绝缘采样时间_IMM21";
CM_ SG_ 2332112300 M2I_Byrack_SysABStTm_IMM21_28 "电压稳定时间_IMM21";
CM_ SG_ 2332112301 CRC_M2I_Byrack_IMM21_29 "CRC校验_IMM21";
CM_ SG_ 2332112301 M2I_Byrack_HVS_IMM21_29 "绝缘测量电压_IMM21";
CM_ SG_ 2332112301 M2I_Byrack_Enable_IMM21_29 "绝缘采样使能位_IMM21";
CM_ SG_ 2332112301 M2I_Byrack_ReVeEnable_IMM21_29 "读取软件版本使能位_IMM21";
CM_ SG_ 2332112301 Reserved_29 "预留预留";
CM_ SG_ 2332112301 M2I_Byrack_IsPostTm_IMM21_29 "绝缘采样时间_IMM21";
CM_ SG_ 2332112301 M2I_Byrack_SysABStTm_IMM21_29 "电压稳定时间_IMM21";
CM_ SG_ 2332112302 CRC_M2I_Byrack_IMM21_30 "CRC校验_IMM21";
CM_ SG_ 2332112302 M2I_Byrack_HVS_IMM21_30 "绝缘测量电压_IMM21";
CM_ SG_ 2332112302 M2I_Byrack_Enable_IMM21_30 "绝缘采样使能位_IMM21";
CM_ SG_ 2332112302 M2I_Byrack_ReVeEnable_IMM21_30 "读取软件版本使能位_IMM21";
CM_ SG_ 2332112302 Reserved_30 "预留预留";
CM_ SG_ 2332112302 M2I_Byrack_IsPostTm_IMM21_30 "绝缘采样时间_IMM21";
CM_ SG_ 2332112302 M2I_Byrack_SysABStTm_IMM21_30 "电压稳定时间_IMM21";
CM_ SG_ 2332112303 CRC_M2I_Byrack_IMM21_31 "CRC校验_IMM21";
CM_ SG_ 2332112303 M2I_Byrack_HVS_IMM21_31 "绝缘测量电压_IMM21";
CM_ SG_ 2332112303 M2I_Byrack_Enable_IMM21_31 "绝缘采样使能位_IMM21";
CM_ SG_ 2332112303 M2I_Byrack_ReVeEnable_IMM21_31 "读取软件版本使能位_IMM21";
CM_ SG_ 2332112303 Reserved_31 "预留预留";
CM_ SG_ 2332112303 M2I_Byrack_IsPostTm_IMM21_31 "绝缘采样时间_IMM21";
CM_ SG_ 2332112303 M2I_Byrack_SysABStTm_IMM21_31 "电压稳定时间_IMM21";
CM_ SG_ 2332112529 CRC_M2I_Byrack_IMM22_01 "CRC校验_IMM22";
CM_ SG_ 2332112529 M2I_Byrack_HVS__IMM22_01 "绝缘测量电压_IMM22";
CM_ SG_ 2332112529 M2I_Byrack_Enable_IMM22_01 "绝缘采样使能位_IMM22";
CM_ SG_ 2332112529 M2I_Byrack_ReVeEnable_IMM22_01 "读取软件版本使能位_IMM22";
CM_ SG_ 2332112529 Reserved_01 "预留预留";
CM_ SG_ 2332112529 M2I_Byrack_IsPostTm_IMM22_01 "绝缘采样时间_IMM22";
CM_ SG_ 2332112529 M2I_Byrack_SysABStTm_IMM22_01 "电压稳定时间_IMM22";
CM_ SG_ 2332112530 CRC_M2I_Byrack_IMM22_02 "CRC校验_IMM22";
CM_ SG_ 2332112530 M2I_Byrack_HVS__IMM22_02 "绝缘测量电压_IMM22";
CM_ SG_ 2332112530 M2I_Byrack_Enable_IMM22_02 "绝缘采样使能位_IMM22";
CM_ SG_ 2332112530 M2I_Byrack_ReVeEnable_IMM22_02 "读取软件版本使能位_IMM22";
CM_ SG_ 2332112530 Reserved_02 "预留预留";
CM_ SG_ 2332112530 M2I_Byrack_IsPostTm_IMM22_02 "绝缘采样时间_IMM22";
CM_ SG_ 2332112530 M2I_Byrack_SysABStTm_IMM22_02 "电压稳定时间_IMM22";
CM_ SG_ 2332112531 CRC_M2I_Byrack_IMM22_03 "CRC校验_IMM22";
CM_ SG_ 2332112531 M2I_Byrack_HVS__IMM22_03 "绝缘测量电压_IMM22";
CM_ SG_ 2332112531 M2I_Byrack_Enable_IMM22_03 "绝缘采样使能位_IMM22";
CM_ SG_ 2332112531 M2I_Byrack_ReVeEnable_IMM22_03 "读取软件版本使能位_IMM22";
CM_ SG_ 2332112531 Reserved_03 "预留预留";
CM_ SG_ 2332112531 M2I_Byrack_IsPostTm_IMM22_03 "绝缘采样时间_IMM22";
CM_ SG_ 2332112531 M2I_Byrack_SysABStTm_IMM22_03 "电压稳定时间_IMM22";
CM_ SG_ 2332112532 CRC_M2I_Byrack_IMM22_04 "CRC校验_IMM22";
CM_ SG_ 2332112532 M2I_Byrack_HVS__IMM22_04 "绝缘测量电压_IMM22";
CM_ SG_ 2332112532 M2I_Byrack_Enable_IMM22_04 "绝缘采样使能位_IMM22";
CM_ SG_ 2332112532 M2I_Byrack_ReVeEnable_IMM22_04 "读取软件版本使能位_IMM22";
CM_ SG_ 2332112532 Reserved_04 "预留预留";
CM_ SG_ 2332112532 M2I_Byrack_IsPostTm_IMM22_04 "绝缘采样时间_IMM22";
CM_ SG_ 2332112532 M2I_Byrack_SysABStTm_IMM22_04 "电压稳定时间_IMM22";
CM_ SG_ 2332112533 CRC_M2I_Byrack_IMM22_05 "CRC校验_IMM22";
CM_ SG_ 2332112533 M2I_Byrack_HVS__IMM22_05 "绝缘测量电压_IMM22";
CM_ SG_ 2332112533 M2I_Byrack_Enable_IMM22_05 "绝缘采样使能位_IMM22";
CM_ SG_ 2332112533 M2I_Byrack_ReVeEnable_IMM22_05 "读取软件版本使能位_IMM22";
CM_ SG_ 2332112533 Reserved_05 "预留预留";
CM_ SG_ 2332112533 M2I_Byrack_IsPostTm_IMM22_05 "绝缘采样时间_IMM22";
CM_ SG_ 2332112533 M2I_Byrack_SysABStTm_IMM22_05 "电压稳定时间_IMM22";
CM_ SG_ 2332112534 CRC_M2I_Byrack_IMM22_06 "CRC校验_IMM22";
CM_ SG_ 2332112534 M2I_Byrack_HVS__IMM22_06 "绝缘测量电压_IMM22";
CM_ SG_ 2332112534 M2I_Byrack_Enable_IMM22_06 "绝缘采样使能位_IMM22";
CM_ SG_ 2332112534 M2I_Byrack_ReVeEnable_IMM22_06 "读取软件版本使能位_IMM22";
CM_ SG_ 2332112534 Reserved_06 "预留预留";
CM_ SG_ 2332112534 M2I_Byrack_IsPostTm_IMM22_06 "绝缘采样时间_IMM22";
CM_ SG_ 2332112534 M2I_Byrack_SysABStTm_IMM22_06 "电压稳定时间_IMM22";
CM_ SG_ 2332112535 CRC_M2I_Byrack_IMM22_07 "CRC校验_IMM22";
CM_ SG_ 2332112535 M2I_Byrack_HVS__IMM22_07 "绝缘测量电压_IMM22";
CM_ SG_ 2332112535 M2I_Byrack_Enable_IMM22_07 "绝缘采样使能位_IMM22";
CM_ SG_ 2332112535 M2I_Byrack_ReVeEnable_IMM22_07 "读取软件版本使能位_IMM22";
CM_ SG_ 2332112535 Reserved_07 "预留预留";
CM_ SG_ 2332112535 M2I_Byrack_IsPostTm_IMM22_07 "绝缘采样时间_IMM22";
CM_ SG_ 2332112535 M2I_Byrack_SysABStTm_IMM22_07 "电压稳定时间_IMM22";
CM_ SG_ 2332112536 CRC_M2I_Byrack_IMM22_08 "CRC校验_IMM22";
CM_ SG_ 2332112536 M2I_Byrack_HVS__IMM22_08 "绝缘测量电压_IMM22";
CM_ SG_ 2332112536 M2I_Byrack_Enable_IMM22_08 "绝缘采样使能位_IMM22";
CM_ SG_ 2332112536 M2I_Byrack_ReVeEnable_IMM22_08 "读取软件版本使能位_IMM22";
CM_ SG_ 2332112536 Reserved_08 "预留预留";
CM_ SG_ 2332112536 M2I_Byrack_IsPostTm_IMM22_08 "绝缘采样时间_IMM22";
CM_ SG_ 2332112536 M2I_Byrack_SysABStTm_IMM22_08 "电压稳定时间_IMM22";
CM_ SG_ 2332112537 CRC_M2I_Byrack_IMM22_09 "CRC校验_IMM22";
CM_ SG_ 2332112537 M2I_Byrack_HVS__IMM22_09 "绝缘测量电压_IMM22";
CM_ SG_ 2332112537 M2I_Byrack_Enable_IMM22_09 "绝缘采样使能位_IMM22";
CM_ SG_ 2332112537 M2I_Byrack_ReVeEnable_IMM22_09 "读取软件版本使能位_IMM22";
CM_ SG_ 2332112537 Reserved_09 "预留预留";
CM_ SG_ 2332112537 M2I_Byrack_IsPostTm_IMM22_09 "绝缘采样时间_IMM22";
CM_ SG_ 2332112537 M2I_Byrack_SysABStTm_IMM22_09 "电压稳定时间_IMM22";
CM_ SG_ 2332112538 CRC_M2I_Byrack_IMM22_10 "CRC校验_IMM22";
CM_ SG_ 2332112538 M2I_Byrack_HVS__IMM22_10 "绝缘测量电压_IMM22";
CM_ SG_ 2332112538 M2I_Byrack_Enable_IMM22_10 "绝缘采样使能位_IMM22";
CM_ SG_ 2332112538 M2I_Byrack_ReVeEnable_IMM22_10 "读取软件版本使能位_IMM22";
CM_ SG_ 2332112538 Reserved_10 "预留预留";
CM_ SG_ 2332112538 M2I_Byrack_IsPostTm_IMM22_10 "绝缘采样时间_IMM22";
CM_ SG_ 2332112538 M2I_Byrack_SysABStTm_IMM22_10 "电压稳定时间_IMM22";
CM_ SG_ 2332112539 CRC_M2I_Byrack_IMM22_11 "CRC校验_IMM22";
CM_ SG_ 2332112539 M2I_Byrack_HVS__IMM22_11 "绝缘测量电压_IMM22";
CM_ SG_ 2332112539 M2I_Byrack_Enable_IMM22_11 "绝缘采样使能位_IMM22";
CM_ SG_ 2332112539 M2I_Byrack_ReVeEnable_IMM22_11 "读取软件版本使能位_IMM22";
CM_ SG_ 2332112539 Reserved_11 "预留预留";
CM_ SG_ 2332112539 M2I_Byrack_IsPostTm_IMM22_11 "绝缘采样时间_IMM22";
CM_ SG_ 2332112539 M2I_Byrack_SysABStTm_IMM22_11 "电压稳定时间_IMM22";
CM_ SG_ 2332112540 CRC_M2I_Byrack_IMM22_12 "CRC校验_IMM22";
CM_ SG_ 2332112540 M2I_Byrack_HVS__IMM22_12 "绝缘测量电压_IMM22";
CM_ SG_ 2332112540 M2I_Byrack_Enable_IMM22_12 "绝缘采样使能位_IMM22";
CM_ SG_ 2332112540 M2I_Byrack_ReVeEnable_IMM22_12 "读取软件版本使能位_IMM22";
CM_ SG_ 2332112540 Reserved_12 "预留预留";
CM_ SG_ 2332112540 M2I_Byrack_IsPostTm_IMM22_12 "绝缘采样时间_IMM22";
CM_ SG_ 2332112540 M2I_Byrack_SysABStTm_IMM22_12 "电压稳定时间_IMM22";
CM_ SG_ 2332112541 CRC_M2I_Byrack_IMM22_13 "CRC校验_IMM22";
CM_ SG_ 2332112541 M2I_Byrack_HVS__IMM22_13 "绝缘测量电压_IMM22";
CM_ SG_ 2332112541 M2I_Byrack_Enable_IMM22_13 "绝缘采样使能位_IMM22";
CM_ SG_ 2332112541 M2I_Byrack_ReVeEnable_IMM22_13 "读取软件版本使能位_IMM22";
CM_ SG_ 2332112541 Reserved_13 "预留预留";
CM_ SG_ 2332112541 M2I_Byrack_IsPostTm_IMM22_13 "绝缘采样时间_IMM22";
CM_ SG_ 2332112541 M2I_Byrack_SysABStTm_IMM22_13 "电压稳定时间_IMM22";
CM_ SG_ 2332112542 CRC_M2I_Byrack_IMM22_14 "CRC校验_IMM22";
CM_ SG_ 2332112542 M2I_Byrack_HVS__IMM22_14 "绝缘测量电压_IMM22";
CM_ SG_ 2332112542 M2I_Byrack_Enable_IMM22_14 "绝缘采样使能位_IMM22";
CM_ SG_ 2332112542 M2I_Byrack_ReVeEnable_IMM22_14 "读取软件版本使能位_IMM22";
CM_ SG_ 2332112542 Reserved_14 "预留预留";
CM_ SG_ 2332112542 M2I_Byrack_IsPostTm_IMM22_14 "绝缘采样时间_IMM22";
CM_ SG_ 2332112542 M2I_Byrack_SysABStTm_IMM22_14 "电压稳定时间_IMM22";
CM_ SG_ 2332112543 CRC_M2I_Byrack_IMM22_15 "CRC校验_IMM22";
CM_ SG_ 2332112543 M2I_Byrack_HVS__IMM22_15 "绝缘测量电压_IMM22";
CM_ SG_ 2332112543 M2I_Byrack_Enable_IMM22_15 "绝缘采样使能位_IMM22";
CM_ SG_ 2332112543 M2I_Byrack_ReVeEnable_IMM22_15 "读取软件版本使能位_IMM22";
CM_ SG_ 2332112543 Reserved_15 "预留预留";
CM_ SG_ 2332112543 M2I_Byrack_IsPostTm_IMM22_15 "绝缘采样时间_IMM22";
CM_ SG_ 2332112543 M2I_Byrack_SysABStTm_IMM22_15 "电压稳定时间_IMM22";
CM_ SG_ 2332112544 CRC_M2I_Byrack_IMM22_16 "CRC校验_IMM22";
CM_ SG_ 2332112544 M2I_Byrack_HVS__IMM22_16 "绝缘测量电压_IMM22";
CM_ SG_ 2332112544 M2I_Byrack_Enable_IMM22_16 "绝缘采样使能位_IMM22";
CM_ SG_ 2332112544 M2I_Byrack_ReVeEnable_IMM22_16 "读取软件版本使能位_IMM22";
CM_ SG_ 2332112544 Reserved_16 "预留预留";
CM_ SG_ 2332112544 M2I_Byrack_IsPostTm_IMM22_16 "绝缘采样时间_IMM22";
CM_ SG_ 2332112544 M2I_Byrack_SysABStTm_IMM22_16 "电压稳定时间_IMM22";
CM_ SG_ 2332112545 CRC_M2I_Byrack_IMM22_17 "CRC校验_IMM22";
CM_ SG_ 2332112545 M2I_Byrack_HVS__IMM22_17 "绝缘测量电压_IMM22";
CM_ SG_ 2332112545 M2I_Byrack_Enable_IMM22_17 "绝缘采样使能位_IMM22";
CM_ SG_ 2332112545 M2I_Byrack_ReVeEnable_IMM22_17 "读取软件版本使能位_IMM22";
CM_ SG_ 2332112545 Reserved_17 "预留预留";
CM_ SG_ 2332112545 M2I_Byrack_IsPostTm_IMM22_17 "绝缘采样时间_IMM22";
CM_ SG_ 2332112545 M2I_Byrack_SysABStTm_IMM22_17 "电压稳定时间_IMM22";
CM_ SG_ 2332112546 CRC_M2I_Byrack_IMM22_18 "CRC校验_IMM22";
CM_ SG_ 2332112546 M2I_Byrack_HVS__IMM22_18 "绝缘测量电压_IMM22";
CM_ SG_ 2332112546 M2I_Byrack_Enable_IMM22_18 "绝缘采样使能位_IMM22";
CM_ SG_ 2332112546 M2I_Byrack_ReVeEnable_IMM22_18 "读取软件版本使能位_IMM22";
CM_ SG_ 2332112546 Reserved_18 "预留预留";
CM_ SG_ 2332112546 M2I_Byrack_IsPostTm_IMM22_18 "绝缘采样时间_IMM22";
CM_ SG_ 2332112546 M2I_Byrack_SysABStTm_IMM22_18 "电压稳定时间_IMM22";
CM_ SG_ 2332112547 CRC_M2I_Byrack_IMM22_19 "CRC校验_IMM22";
CM_ SG_ 2332112547 M2I_Byrack_HVS__IMM22_19 "绝缘测量电压_IMM22";
CM_ SG_ 2332112547 M2I_Byrack_Enable_IMM22_19 "绝缘采样使能位_IMM22";
CM_ SG_ 2332112547 M2I_Byrack_ReVeEnable_IMM22_19 "读取软件版本使能位_IMM22";
CM_ SG_ 2332112547 Reserved_19 "预留预留";
CM_ SG_ 2332112547 M2I_Byrack_IsPostTm_IMM22_19 "绝缘采样时间_IMM22";
CM_ SG_ 2332112547 M2I_Byrack_SysABStTm_IMM22_19 "电压稳定时间_IMM22";
CM_ SG_ 2332112548 CRC_M2I_Byrack_IMM22_20 "CRC校验_IMM22";
CM_ SG_ 2332112548 M2I_Byrack_HVS__IMM22_20 "绝缘测量电压_IMM22";
CM_ SG_ 2332112548 M2I_Byrack_Enable_IMM22_20 "绝缘采样使能位_IMM22";
CM_ SG_ 2332112548 M2I_Byrack_ReVeEnable_IMM22_20 "读取软件版本使能位_IMM22";
CM_ SG_ 2332112548 Reserved_20 "预留预留";
CM_ SG_ 2332112548 M2I_Byrack_IsPostTm_IMM22_20 "绝缘采样时间_IMM22";
CM_ SG_ 2332112548 M2I_Byrack_SysABStTm_IMM22_20 "电压稳定时间_IMM22";
CM_ SG_ 2332112549 CRC_M2I_Byrack_IMM22_21 "CRC校验_IMM22";
CM_ SG_ 2332112549 M2I_Byrack_HVS__IMM22_21 "绝缘测量电压_IMM22";
CM_ SG_ 2332112549 M2I_Byrack_Enable_IMM22_21 "绝缘采样使能位_IMM22";
CM_ SG_ 2332112549 M2I_Byrack_ReVeEnable_IMM22_21 "读取软件版本使能位_IMM22";
CM_ SG_ 2332112549 Reserved_21 "预留预留";
CM_ SG_ 2332112549 M2I_Byrack_IsPostTm_IMM22_21 "绝缘采样时间_IMM22";
CM_ SG_ 2332112549 M2I_Byrack_SysABStTm_IMM22_21 "电压稳定时间_IMM22";
CM_ SG_ 2332112550 CRC_M2I_Byrack_IMM22_22 "CRC校验_IMM22";
CM_ SG_ 2332112550 M2I_Byrack_HVS__IMM22_22 "绝缘测量电压_IMM22";
CM_ SG_ 2332112550 M2I_Byrack_Enable_IMM22_22 "绝缘采样使能位_IMM22";
CM_ SG_ 2332112550 M2I_Byrack_ReVeEnable_IMM22_22 "读取软件版本使能位_IMM22";
CM_ SG_ 2332112550 Reserved_22 "预留预留";
CM_ SG_ 2332112550 M2I_Byrack_IsPostTm_IMM22_22 "绝缘采样时间_IMM22";
CM_ SG_ 2332112550 M2I_Byrack_SysABStTm_IMM22_22 "电压稳定时间_IMM22";
CM_ SG_ 2332112551 CRC_M2I_Byrack_IMM22_23 "CRC校验_IMM22";
CM_ SG_ 2332112551 M2I_Byrack_HVS__IMM22_23 "绝缘测量电压_IMM22";
CM_ SG_ 2332112551 M2I_Byrack_Enable_IMM22_23 "绝缘采样使能位_IMM22";
CM_ SG_ 2332112551 M2I_Byrack_ReVeEnable_IMM22_23 "读取软件版本使能位_IMM22";
CM_ SG_ 2332112551 Reserved_23 "预留预留";
CM_ SG_ 2332112551 M2I_Byrack_IsPostTm_IMM22_23 "绝缘采样时间_IMM22";
CM_ SG_ 2332112551 M2I_Byrack_SysABStTm_IMM22_23 "电压稳定时间_IMM22";
CM_ SG_ 2332112552 CRC_M2I_Byrack_IMM22_24 "CRC校验_IMM22";
CM_ SG_ 2332112552 M2I_Byrack_HVS__IMM22_24 "绝缘测量电压_IMM22";
CM_ SG_ 2332112552 M2I_Byrack_Enable_IMM22_24 "绝缘采样使能位_IMM22";
CM_ SG_ 2332112552 M2I_Byrack_ReVeEnable_IMM22_24 "读取软件版本使能位_IMM22";
CM_ SG_ 2332112552 Reserved_24 "预留预留";
CM_ SG_ 2332112552 M2I_Byrack_IsPostTm_IMM22_24 "绝缘采样时间_IMM22";
CM_ SG_ 2332112552 M2I_Byrack_SysABStTm_IMM22_24 "电压稳定时间_IMM22";
CM_ SG_ 2332112553 CRC_M2I_Byrack_IMM22_25 "CRC校验_IMM22";
CM_ SG_ 2332112553 M2I_Byrack_HVS__IMM22_25 "绝缘测量电压_IMM22";
CM_ SG_ 2332112553 M2I_Byrack_Enable_IMM22_25 "绝缘采样使能位_IMM22";
CM_ SG_ 2332112553 M2I_Byrack_ReVeEnable_IMM22_25 "读取软件版本使能位_IMM22";
CM_ SG_ 2332112553 Reserved_25 "预留预留";
CM_ SG_ 2332112553 M2I_Byrack_IsPostTm_IMM22_25 "绝缘采样时间_IMM22";
CM_ SG_ 2332112553 M2I_Byrack_SysABStTm_IMM22_25 "电压稳定时间_IMM22";
CM_ SG_ 2332112554 CRC_M2I_Byrack_IMM22_26 "CRC校验_IMM22";
CM_ SG_ 2332112554 M2I_Byrack_HVS__IMM22_26 "绝缘测量电压_IMM22";
CM_ SG_ 2332112554 M2I_Byrack_Enable_IMM22_26 "绝缘采样使能位_IMM22";
CM_ SG_ 2332112554 M2I_Byrack_ReVeEnable_IMM22_26 "读取软件版本使能位_IMM22";
CM_ SG_ 2332112554 Reserved_26 "预留预留";
CM_ SG_ 2332112554 M2I_Byrack_IsPostTm_IMM22_26 "绝缘采样时间_IMM22";
CM_ SG_ 2332112554 M2I_Byrack_SysABStTm_IMM22_26 "电压稳定时间_IMM22";
CM_ SG_ 2332112555 CRC_M2I_Byrack_IMM22_27 "CRC校验_IMM22";
CM_ SG_ 2332112555 M2I_Byrack_HVS__IMM22_27 "绝缘测量电压_IMM22";
CM_ SG_ 2332112555 M2I_Byrack_Enable_IMM22_27 "绝缘采样使能位_IMM22";
CM_ SG_ 2332112555 M2I_Byrack_ReVeEnable_IMM22_27 "读取软件版本使能位_IMM22";
CM_ SG_ 2332112555 Reserved_27 "预留预留";
CM_ SG_ 2332112555 M2I_Byrack_IsPostTm_IMM22_27 "绝缘采样时间_IMM22";
CM_ SG_ 2332112555 M2I_Byrack_SysABStTm_IMM22_27 "电压稳定时间_IMM22";
CM_ SG_ 2332112556 CRC_M2I_Byrack_IMM22_28 "CRC校验_IMM22";
CM_ SG_ 2332112556 M2I_Byrack_HVS__IMM22_28 "绝缘测量电压_IMM22";
CM_ SG_ 2332112556 M2I_Byrack_Enable_IMM22_28 "绝缘采样使能位_IMM22";
CM_ SG_ 2332112556 M2I_Byrack_ReVeEnable_IMM22_28 "读取软件版本使能位_IMM22";
CM_ SG_ 2332112556 Reserved_28 "预留预留";
CM_ SG_ 2332112556 M2I_Byrack_IsPostTm_IMM22_28 "绝缘采样时间_IMM22";
CM_ SG_ 2332112556 M2I_Byrack_SysABStTm_IMM22_28 "电压稳定时间_IMM22";
CM_ SG_ 2332112557 CRC_M2I_Byrack_IMM22_29 "CRC校验_IMM22";
CM_ SG_ 2332112557 M2I_Byrack_HVS__IMM22_29 "绝缘测量电压_IMM22";
CM_ SG_ 2332112557 M2I_Byrack_Enable_IMM22_29 "绝缘采样使能位_IMM22";
CM_ SG_ 2332112557 M2I_Byrack_ReVeEnable_IMM22_29 "读取软件版本使能位_IMM22";
CM_ SG_ 2332112557 Reserved_29 "预留预留";
CM_ SG_ 2332112557 M2I_Byrack_IsPostTm_IMM22_29 "绝缘采样时间_IMM22";
CM_ SG_ 2332112557 M2I_Byrack_SysABStTm_IMM22_29 "电压稳定时间_IMM22";
CM_ SG_ 2332112558 CRC_M2I_Byrack_IMM22_30 "CRC校验_IMM22";
CM_ SG_ 2332112558 M2I_Byrack_HVS__IMM22_30 "绝缘测量电压_IMM22";
CM_ SG_ 2332112558 M2I_Byrack_Enable_IMM22_30 "绝缘采样使能位_IMM22";
CM_ SG_ 2332112558 M2I_Byrack_ReVeEnable_IMM22_30 "读取软件版本使能位_IMM22";
CM_ SG_ 2332112558 Reserved_30 "预留预留";
CM_ SG_ 2332112558 M2I_Byrack_IsPostTm_IMM22_30 "绝缘采样时间_IMM22";
CM_ SG_ 2332112558 M2I_Byrack_SysABStTm_IMM22_30 "电压稳定时间_IMM22";
CM_ SG_ 2332112559 CRC_M2I_Byrack_IMM22_31 "CRC校验_IMM22";
CM_ SG_ 2332112559 M2I_Byrack_HVS__IMM22_31 "绝缘测量电压_IMM22";
CM_ SG_ 2332112559 M2I_Byrack_Enable_IMM22_31 "绝缘采样使能位_IMM22";
CM_ SG_ 2332112559 M2I_Byrack_ReVeEnable_IMM22_31 "读取软件版本使能位_IMM22";
CM_ SG_ 2332112559 Reserved_31 "预留预留";
CM_ SG_ 2332112559 M2I_Byrack_IsPostTm_IMM22_31 "绝缘采样时间_IMM22";
CM_ SG_ 2332112559 M2I_Byrack_SysABStTm_IMM22_31 "电压稳定时间_IMM22";
CM_ SG_ 2332112785 CRC_M2I_Byrack_IMM23_01 "CRC校验_IMM23";
CM_ SG_ 2332112785 M2I_Byrack_HVS__IMM23_01 "绝缘测量电压_IMM23";
CM_ SG_ 2332112785 M2I_Byrack_Enable_IMM23_01 "绝缘采样使能位_IMM23";
CM_ SG_ 2332112785 M2I_Byrack_ReVeEnable_IMM23_01 "读取软件版本使能位_IMM23";
CM_ SG_ 2332112785 Reserved_01 "预留预留";
CM_ SG_ 2332112785 M2I_Byrack_IsPostTm_IMM23_01 "绝缘采样时间_IMM23";
CM_ SG_ 2332112785 M2I_Byrack_SysABStTm_IMM23_01 "电压稳定时间_IMM23";
CM_ SG_ 2332112786 CRC_M2I_Byrack_IMM23_02 "CRC校验_IMM23";
CM_ SG_ 2332112786 M2I_Byrack_HVS__IMM23_02 "绝缘测量电压_IMM23";
CM_ SG_ 2332112786 M2I_Byrack_Enable_IMM23_02 "绝缘采样使能位_IMM23";
CM_ SG_ 2332112786 M2I_Byrack_ReVeEnable_IMM23_02 "读取软件版本使能位_IMM23";
CM_ SG_ 2332112786 Reserved_02 "预留预留";
CM_ SG_ 2332112786 M2I_Byrack_IsPostTm_IMM23_02 "绝缘采样时间_IMM23";
CM_ SG_ 2332112786 M2I_Byrack_SysABStTm_IMM23_02 "电压稳定时间_IMM23";
CM_ SG_ 2332112787 CRC_M2I_Byrack_IMM23_03 "CRC校验_IMM23";
CM_ SG_ 2332112787 M2I_Byrack_HVS__IMM23_03 "绝缘测量电压_IMM23";
CM_ SG_ 2332112787 M2I_Byrack_Enable_IMM23_03 "绝缘采样使能位_IMM23";
CM_ SG_ 2332112787 M2I_Byrack_ReVeEnable_IMM23_03 "读取软件版本使能位_IMM23";
CM_ SG_ 2332112787 Reserved_03 "预留预留";
CM_ SG_ 2332112787 M2I_Byrack_IsPostTm_IMM23_03 "绝缘采样时间_IMM23";
CM_ SG_ 2332112787 M2I_Byrack_SysABStTm_IMM23_03 "电压稳定时间_IMM23";
CM_ SG_ 2332112788 CRC_M2I_Byrack_IMM23_04 "CRC校验_IMM23";
CM_ SG_ 2332112788 M2I_Byrack_HVS__IMM23_04 "绝缘测量电压_IMM23";
CM_ SG_ 2332112788 M2I_Byrack_Enable_IMM23_04 "绝缘采样使能位_IMM23";
CM_ SG_ 2332112788 M2I_Byrack_ReVeEnable_IMM23_04 "读取软件版本使能位_IMM23";
CM_ SG_ 2332112788 Reserved_04 "预留预留";
CM_ SG_ 2332112788 M2I_Byrack_IsPostTm_IMM23_04 "绝缘采样时间_IMM23";
CM_ SG_ 2332112788 M2I_Byrack_SysABStTm_IMM23_04 "电压稳定时间_IMM23";
CM_ SG_ 2332112789 CRC_M2I_Byrack_IMM23_05 "CRC校验_IMM23";
CM_ SG_ 2332112789 M2I_Byrack_HVS__IMM23_05 "绝缘测量电压_IMM23";
CM_ SG_ 2332112789 M2I_Byrack_Enable_IMM23_05 "绝缘采样使能位_IMM23";
CM_ SG_ 2332112789 M2I_Byrack_ReVeEnable_IMM23_05 "读取软件版本使能位_IMM23";
CM_ SG_ 2332112789 Reserved_05 "预留预留";
CM_ SG_ 2332112789 M2I_Byrack_IsPostTm_IMM23_05 "绝缘采样时间_IMM23";
CM_ SG_ 2332112789 M2I_Byrack_SysABStTm_IMM23_05 "电压稳定时间_IMM23";
CM_ SG_ 2332112790 CRC_M2I_Byrack_IMM23_06 "CRC校验_IMM23";
CM_ SG_ 2332112790 M2I_Byrack_HVS__IMM23_06 "绝缘测量电压_IMM23";
CM_ SG_ 2332112790 M2I_Byrack_Enable_IMM23_06 "绝缘采样使能位_IMM23";
CM_ SG_ 2332112790 M2I_Byrack_ReVeEnable_IMM23_06 "读取软件版本使能位_IMM23";
CM_ SG_ 2332112790 Reserved_06 "预留预留";
CM_ SG_ 2332112790 M2I_Byrack_IsPostTm_IMM23_06 "绝缘采样时间_IMM23";
CM_ SG_ 2332112790 M2I_Byrack_SysABStTm_IMM23_06 "电压稳定时间_IMM23";
CM_ SG_ 2332112791 CRC_M2I_Byrack_IMM23_07 "CRC校验_IMM23";
CM_ SG_ 2332112791 M2I_Byrack_HVS__IMM23_07 "绝缘测量电压_IMM23";
CM_ SG_ 2332112791 M2I_Byrack_Enable_IMM23_07 "绝缘采样使能位_IMM23";
CM_ SG_ 2332112791 M2I_Byrack_ReVeEnable_IMM23_07 "读取软件版本使能位_IMM23";
CM_ SG_ 2332112791 Reserved_07 "预留预留";
CM_ SG_ 2332112791 M2I_Byrack_IsPostTm_IMM23_07 "绝缘采样时间_IMM23";
CM_ SG_ 2332112791 M2I_Byrack_SysABStTm_IMM23_07 "电压稳定时间_IMM23";
CM_ SG_ 2332112792 CRC_M2I_Byrack_IMM23_08 "CRC校验_IMM23";
CM_ SG_ 2332112792 M2I_Byrack_HVS__IMM23_08 "绝缘测量电压_IMM23";
CM_ SG_ 2332112792 M2I_Byrack_Enable_IMM23_08 "绝缘采样使能位_IMM23";
CM_ SG_ 2332112792 M2I_Byrack_ReVeEnable_IMM23_08 "读取软件版本使能位_IMM23";
CM_ SG_ 2332112792 Reserved_08 "预留预留";
CM_ SG_ 2332112792 M2I_Byrack_IsPostTm_IMM23_08 "绝缘采样时间_IMM23";
CM_ SG_ 2332112792 M2I_Byrack_SysABStTm_IMM23_08 "电压稳定时间_IMM23";
CM_ SG_ 2332112793 CRC_M2I_Byrack_IMM23_09 "CRC校验_IMM23";
CM_ SG_ 2332112793 M2I_Byrack_HVS__IMM23_09 "绝缘测量电压_IMM23";
CM_ SG_ 2332112793 M2I_Byrack_Enable_IMM23_09 "绝缘采样使能位_IMM23";
CM_ SG_ 2332112793 M2I_Byrack_ReVeEnable_IMM23_09 "读取软件版本使能位_IMM23";
CM_ SG_ 2332112793 Reserved_09 "预留预留";
CM_ SG_ 2332112793 M2I_Byrack_IsPostTm_IMM23_09 "绝缘采样时间_IMM23";
CM_ SG_ 2332112793 M2I_Byrack_SysABStTm_IMM23_09 "电压稳定时间_IMM23";
CM_ SG_ 2332112794 CRC_M2I_Byrack_IMM23_10 "CRC校验_IMM23";
CM_ SG_ 2332112794 M2I_Byrack_HVS__IMM23_10 "绝缘测量电压_IMM23";
CM_ SG_ 2332112794 M2I_Byrack_Enable_IMM23_10 "绝缘采样使能位_IMM23";
CM_ SG_ 2332112794 M2I_Byrack_ReVeEnable_IMM23_10 "读取软件版本使能位_IMM23";
CM_ SG_ 2332112794 Reserved_10 "预留预留";
CM_ SG_ 2332112794 M2I_Byrack_IsPostTm_IMM23_10 "绝缘采样时间_IMM23";
CM_ SG_ 2332112794 M2I_Byrack_SysABStTm_IMM23_10 "电压稳定时间_IMM23";
CM_ SG_ 2332112795 CRC_M2I_Byrack_IMM23_11 "CRC校验_IMM23";
CM_ SG_ 2332112795 M2I_Byrack_HVS__IMM23_11 "绝缘测量电压_IMM23";
CM_ SG_ 2332112795 M2I_Byrack_Enable_IMM23_11 "绝缘采样使能位_IMM23";
CM_ SG_ 2332112795 M2I_Byrack_ReVeEnable_IMM23_11 "读取软件版本使能位_IMM23";
CM_ SG_ 2332112795 Reserved_11 "预留预留";
CM_ SG_ 2332112795 M2I_Byrack_IsPostTm_IMM23_11 "绝缘采样时间_IMM23";
CM_ SG_ 2332112795 M2I_Byrack_SysABStTm_IMM23_11 "电压稳定时间_IMM23";
CM_ SG_ 2332112796 CRC_M2I_Byrack_IMM23_12 "CRC校验_IMM23";
CM_ SG_ 2332112796 M2I_Byrack_HVS__IMM23_12 "绝缘测量电压_IMM23";
CM_ SG_ 2332112796 M2I_Byrack_Enable_IMM23_12 "绝缘采样使能位_IMM23";
CM_ SG_ 2332112796 M2I_Byrack_ReVeEnable_IMM23_12 "读取软件版本使能位_IMM23";
CM_ SG_ 2332112796 Reserved_12 "预留预留";
CM_ SG_ 2332112796 M2I_Byrack_IsPostTm_IMM23_12 "绝缘采样时间_IMM23";
CM_ SG_ 2332112796 M2I_Byrack_SysABStTm_IMM23_12 "电压稳定时间_IMM23";
CM_ SG_ 2332112797 CRC_M2I_Byrack_IMM23_13 "CRC校验_IMM23";
CM_ SG_ 2332112797 M2I_Byrack_HVS__IMM23_13 "绝缘测量电压_IMM23";
CM_ SG_ 2332112797 M2I_Byrack_Enable_IMM23_13 "绝缘采样使能位_IMM23";
CM_ SG_ 2332112797 M2I_Byrack_ReVeEnable_IMM23_13 "读取软件版本使能位_IMM23";
CM_ SG_ 2332112797 Reserved_13 "预留预留";
CM_ SG_ 2332112797 M2I_Byrack_IsPostTm_IMM23_13 "绝缘采样时间_IMM23";
CM_ SG_ 2332112797 M2I_Byrack_SysABStTm_IMM23_13 "电压稳定时间_IMM23";
CM_ SG_ 2332112798 CRC_M2I_Byrack_IMM23_14 "CRC校验_IMM23";
CM_ SG_ 2332112798 M2I_Byrack_HVS__IMM23_14 "绝缘测量电压_IMM23";
CM_ SG_ 2332112798 M2I_Byrack_Enable_IMM23_14 "绝缘采样使能位_IMM23";
CM_ SG_ 2332112798 M2I_Byrack_ReVeEnable_IMM23_14 "读取软件版本使能位_IMM23";
CM_ SG_ 2332112798 Reserved_14 "预留预留";
CM_ SG_ 2332112798 M2I_Byrack_IsPostTm_IMM23_14 "绝缘采样时间_IMM23";
CM_ SG_ 2332112798 M2I_Byrack_SysABStTm_IMM23_14 "电压稳定时间_IMM23";
CM_ SG_ 2332112799 CRC_M2I_Byrack_IMM23_15 "CRC校验_IMM23";
CM_ SG_ 2332112799 M2I_Byrack_HVS__IMM23_15 "绝缘测量电压_IMM23";
CM_ SG_ 2332112799 M2I_Byrack_Enable_IMM23_15 "绝缘采样使能位_IMM23";
CM_ SG_ 2332112799 M2I_Byrack_ReVeEnable_IMM23_15 "读取软件版本使能位_IMM23";
CM_ SG_ 2332112799 Reserved_15 "预留预留";
CM_ SG_ 2332112799 M2I_Byrack_IsPostTm_IMM23_15 "绝缘采样时间_IMM23";
CM_ SG_ 2332112799 M2I_Byrack_SysABStTm_IMM23_15 "电压稳定时间_IMM23";
CM_ SG_ 2332112800 CRC_M2I_Byrack_IMM23_16 "CRC校验_IMM23";
CM_ SG_ 2332112800 M2I_Byrack_HVS__IMM23_16 "绝缘测量电压_IMM23";
CM_ SG_ 2332112800 M2I_Byrack_Enable_IMM23_16 "绝缘采样使能位_IMM23";
CM_ SG_ 2332112800 M2I_Byrack_ReVeEnable_IMM23_16 "读取软件版本使能位_IMM23";
CM_ SG_ 2332112800 Reserved_16 "预留预留";
CM_ SG_ 2332112800 M2I_Byrack_IsPostTm_IMM23_16 "绝缘采样时间_IMM23";
CM_ SG_ 2332112800 M2I_Byrack_SysABStTm_IMM23_16 "电压稳定时间_IMM23";
CM_ SG_ 2332112801 CRC_M2I_Byrack_IMM23_17 "CRC校验_IMM23";
CM_ SG_ 2332112801 M2I_Byrack_HVS__IMM23_17 "绝缘测量电压_IMM23";
CM_ SG_ 2332112801 M2I_Byrack_Enable_IMM23_17 "绝缘采样使能位_IMM23";
CM_ SG_ 2332112801 M2I_Byrack_ReVeEnable_IMM23_17 "读取软件版本使能位_IMM23";
CM_ SG_ 2332112801 Reserved_17 "预留预留";
CM_ SG_ 2332112801 M2I_Byrack_IsPostTm_IMM23_17 "绝缘采样时间_IMM23";
CM_ SG_ 2332112801 M2I_Byrack_SysABStTm_IMM23_17 "电压稳定时间_IMM23";
CM_ SG_ 2332112802 CRC_M2I_Byrack_IMM23_18 "CRC校验_IMM23";
CM_ SG_ 2332112802 M2I_Byrack_HVS__IMM23_18 "绝缘测量电压_IMM23";
CM_ SG_ 2332112802 M2I_Byrack_Enable_IMM23_18 "绝缘采样使能位_IMM23";
CM_ SG_ 2332112802 M2I_Byrack_ReVeEnable_IMM23_18 "读取软件版本使能位_IMM23";
CM_ SG_ 2332112802 Reserved_18 "预留预留";
CM_ SG_ 2332112802 M2I_Byrack_IsPostTm_IMM23_18 "绝缘采样时间_IMM23";
CM_ SG_ 2332112802 M2I_Byrack_SysABStTm_IMM23_18 "电压稳定时间_IMM23";
CM_ SG_ 2332112803 CRC_M2I_Byrack_IMM23_19 "CRC校验_IMM23";
CM_ SG_ 2332112803 M2I_Byrack_HVS__IMM23_19 "绝缘测量电压_IMM23";
CM_ SG_ 2332112803 M2I_Byrack_Enable_IMM23_19 "绝缘采样使能位_IMM23";
CM_ SG_ 2332112803 M2I_Byrack_ReVeEnable_IMM23_19 "读取软件版本使能位_IMM23";
CM_ SG_ 2332112803 Reserved_19 "预留预留";
CM_ SG_ 2332112803 M2I_Byrack_IsPostTm_IMM23_19 "绝缘采样时间_IMM23";
CM_ SG_ 2332112803 M2I_Byrack_SysABStTm_IMM23_19 "电压稳定时间_IMM23";
CM_ SG_ 2332112804 CRC_M2I_Byrack_IMM23_20 "CRC校验_IMM23";
CM_ SG_ 2332112804 M2I_Byrack_HVS__IMM23_20 "绝缘测量电压_IMM23";
CM_ SG_ 2332112804 M2I_Byrack_Enable_IMM23_20 "绝缘采样使能位_IMM23";
CM_ SG_ 2332112804 M2I_Byrack_ReVeEnable_IMM23_20 "读取软件版本使能位_IMM23";
CM_ SG_ 2332112804 Reserved_20 "预留预留";
CM_ SG_ 2332112804 M2I_Byrack_IsPostTm_IMM23_20 "绝缘采样时间_IMM23";
CM_ SG_ 2332112804 M2I_Byrack_SysABStTm_IMM23_20 "电压稳定时间_IMM23";
CM_ SG_ 2332112805 CRC_M2I_Byrack_IMM23_21 "CRC校验_IMM23";
CM_ SG_ 2332112805 M2I_Byrack_HVS__IMM23_21 "绝缘测量电压_IMM23";
CM_ SG_ 2332112805 M2I_Byrack_Enable_IMM23_21 "绝缘采样使能位_IMM23";
CM_ SG_ 2332112805 M2I_Byrack_ReVeEnable_IMM23_21 "读取软件版本使能位_IMM23";
CM_ SG_ 2332112805 Reserved_21 "预留预留";
CM_ SG_ 2332112805 M2I_Byrack_IsPostTm_IMM23_21 "绝缘采样时间_IMM23";
CM_ SG_ 2332112805 M2I_Byrack_SysABStTm_IMM23_21 "电压稳定时间_IMM23";
CM_ SG_ 2332112806 CRC_M2I_Byrack_IMM23_22 "CRC校验_IMM23";
CM_ SG_ 2332112806 M2I_Byrack_HVS__IMM23_22 "绝缘测量电压_IMM23";
CM_ SG_ 2332112806 M2I_Byrack_Enable_IMM23_22 "绝缘采样使能位_IMM23";
CM_ SG_ 2332112806 M2I_Byrack_ReVeEnable_IMM23_22 "读取软件版本使能位_IMM23";
CM_ SG_ 2332112806 Reserved_22 "预留预留";
CM_ SG_ 2332112806 M2I_Byrack_IsPostTm_IMM23_22 "绝缘采样时间_IMM23";
CM_ SG_ 2332112806 M2I_Byrack_SysABStTm_IMM23_22 "电压稳定时间_IMM23";
CM_ SG_ 2332112807 CRC_M2I_Byrack_IMM23_23 "CRC校验_IMM23";
CM_ SG_ 2332112807 M2I_Byrack_HVS__IMM23_23 "绝缘测量电压_IMM23";
CM_ SG_ 2332112807 M2I_Byrack_Enable_IMM23_23 "绝缘采样使能位_IMM23";
CM_ SG_ 2332112807 M2I_Byrack_ReVeEnable_IMM23_23 "读取软件版本使能位_IMM23";
CM_ SG_ 2332112807 Reserved_23 "预留预留";
CM_ SG_ 2332112807 M2I_Byrack_IsPostTm_IMM23_23 "绝缘采样时间_IMM23";
CM_ SG_ 2332112807 M2I_Byrack_SysABStTm_IMM23_23 "电压稳定时间_IMM23";
CM_ SG_ 2332112808 CRC_M2I_Byrack_IMM23_24 "CRC校验_IMM23";
CM_ SG_ 2332112808 M2I_Byrack_HVS__IMM23_24 "绝缘测量电压_IMM23";
CM_ SG_ 2332112808 M2I_Byrack_Enable_IMM23_24 "绝缘采样使能位_IMM23";
CM_ SG_ 2332112808 M2I_Byrack_ReVeEnable_IMM23_24 "读取软件版本使能位_IMM23";
CM_ SG_ 2332112808 Reserved_24 "预留预留";
CM_ SG_ 2332112808 M2I_Byrack_IsPostTm_IMM23_24 "绝缘采样时间_IMM23";
CM_ SG_ 2332112808 M2I_Byrack_SysABStTm_IMM23_24 "电压稳定时间_IMM23";
CM_ SG_ 2332112809 CRC_M2I_Byrack_IMM23_25 "CRC校验_IMM23";
CM_ SG_ 2332112809 M2I_Byrack_HVS__IMM23_25 "绝缘测量电压_IMM23";
CM_ SG_ 2332112809 M2I_Byrack_Enable_IMM23_25 "绝缘采样使能位_IMM23";
CM_ SG_ 2332112809 M2I_Byrack_ReVeEnable_IMM23_25 "读取软件版本使能位_IMM23";
CM_ SG_ 2332112809 Reserved_25 "预留预留";
CM_ SG_ 2332112809 M2I_Byrack_IsPostTm_IMM23_25 "绝缘采样时间_IMM23";
CM_ SG_ 2332112809 M2I_Byrack_SysABStTm_IMM23_25 "电压稳定时间_IMM23";
CM_ SG_ 2332112810 CRC_M2I_Byrack_IMM23_26 "CRC校验_IMM23";
CM_ SG_ 2332112810 M2I_Byrack_HVS__IMM23_26 "绝缘测量电压_IMM23";
CM_ SG_ 2332112810 M2I_Byrack_Enable_IMM23_26 "绝缘采样使能位_IMM23";
CM_ SG_ 2332112810 M2I_Byrack_ReVeEnable_IMM23_26 "读取软件版本使能位_IMM23";
CM_ SG_ 2332112810 Reserved_26 "预留预留";
CM_ SG_ 2332112810 M2I_Byrack_IsPostTm_IMM23_26 "绝缘采样时间_IMM23";
CM_ SG_ 2332112810 M2I_Byrack_SysABStTm_IMM23_26 "电压稳定时间_IMM23";
CM_ SG_ 2332112811 CRC_M2I_Byrack_IMM23_27 "CRC校验_IMM23";
CM_ SG_ 2332112811 M2I_Byrack_HVS__IMM23_27 "绝缘测量电压_IMM23";
CM_ SG_ 2332112811 M2I_Byrack_Enable_IMM23_27 "绝缘采样使能位_IMM23";
CM_ SG_ 2332112811 M2I_Byrack_ReVeEnable_IMM23_27 "读取软件版本使能位_IMM23";
CM_ SG_ 2332112811 Reserved_27 "预留预留";
CM_ SG_ 2332112811 M2I_Byrack_IsPostTm_IMM23_27 "绝缘采样时间_IMM23";
CM_ SG_ 2332112811 M2I_Byrack_SysABStTm_IMM23_27 "电压稳定时间_IMM23";
CM_ SG_ 2332112812 CRC_M2I_Byrack_IMM23_28 "CRC校验_IMM23";
CM_ SG_ 2332112812 M2I_Byrack_HVS__IMM23_28 "绝缘测量电压_IMM23";
CM_ SG_ 2332112812 M2I_Byrack_Enable_IMM23_28 "绝缘采样使能位_IMM23";
CM_ SG_ 2332112812 M2I_Byrack_ReVeEnable_IMM23_28 "读取软件版本使能位_IMM23";
CM_ SG_ 2332112812 Reserved_28 "预留预留";
CM_ SG_ 2332112812 M2I_Byrack_IsPostTm_IMM23_28 "绝缘采样时间_IMM23";
CM_ SG_ 2332112812 M2I_Byrack_SysABStTm_IMM23_28 "电压稳定时间_IMM23";
CM_ SG_ 2332112813 CRC_M2I_Byrack_IMM23_29 "CRC校验_IMM23";
CM_ SG_ 2332112813 M2I_Byrack_HVS__IMM23_29 "绝缘测量电压_IMM23";
CM_ SG_ 2332112813 M2I_Byrack_Enable_IMM23_29 "绝缘采样使能位_IMM23";
CM_ SG_ 2332112813 M2I_Byrack_ReVeEnable_IMM23_29 "读取软件版本使能位_IMM23";
CM_ SG_ 2332112813 Reserved_29 "预留预留";
CM_ SG_ 2332112813 M2I_Byrack_IsPostTm_IMM23_29 "绝缘采样时间_IMM23";
CM_ SG_ 2332112813 M2I_Byrack_SysABStTm_IMM23_29 "电压稳定时间_IMM23";
CM_ SG_ 2332112814 CRC_M2I_Byrack_IMM23_30 "CRC校验_IMM23";
CM_ SG_ 2332112814 M2I_Byrack_HVS__IMM23_30 "绝缘测量电压_IMM23";
CM_ SG_ 2332112814 M2I_Byrack_Enable_IMM23_30 "绝缘采样使能位_IMM23";
CM_ SG_ 2332112814 M2I_Byrack_ReVeEnable_IMM23_30 "读取软件版本使能位_IMM23";
CM_ SG_ 2332112814 Reserved_30 "预留预留";
CM_ SG_ 2332112814 M2I_Byrack_IsPostTm_IMM23_30 "绝缘采样时间_IMM23";
CM_ SG_ 2332112814 M2I_Byrack_SysABStTm_IMM23_30 "电压稳定时间_IMM23";
CM_ SG_ 2332112815 CRC_M2I_Byrack_IMM23_31 "CRC校验_IMM23";
CM_ SG_ 2332112815 M2I_Byrack_HVS__IMM23_31 "绝缘测量电压_IMM23";
CM_ SG_ 2332112815 M2I_Byrack_Enable_IMM23_31 "绝缘采样使能位_IMM23";
CM_ SG_ 2332112815 M2I_Byrack_ReVeEnable_IMM23_31 "读取软件版本使能位_IMM23";
CM_ SG_ 2332112815 Reserved_31 "预留预留";
CM_ SG_ 2332112815 M2I_Byrack_IsPostTm_IMM23_31 "绝缘采样时间_IMM23";
CM_ SG_ 2332112815 M2I_Byrack_SysABStTm_IMM23_31 "电压稳定时间_IMM23";
CM_ SG_ 2332113041 CRC_M2I_Byrack_IMM24_01 "CRC校验_IMM24";
CM_ SG_ 2332113041 M2I_Byrack_HVS_IMM24_01 "绝缘测量电压_IMM24";
CM_ SG_ 2332113041 M2I_Byrack_Enable_IMM24_01 "绝缘采样使能位_IMM24";
CM_ SG_ 2332113041 M2I_Byrack_ReVeEnable_IMM24_01 "读取软件版本使能位_IMM24";
CM_ SG_ 2332113041 Reserved_01 "预留预留";
CM_ SG_ 2332113041 M2I_Byrack_IsPostTm_IMM24_01 "绝缘采样时间_IMM24";
CM_ SG_ 2332113041 M2I_Byrack_SysABStTm_IMM24_01 "电压稳定时间_IMM24";
CM_ SG_ 2332113042 CRC_M2I_Byrack_IMM24_02 "CRC校验_IMM24";
CM_ SG_ 2332113042 M2I_Byrack_HVS_IMM24_02 "绝缘测量电压_IMM24";
CM_ SG_ 2332113042 M2I_Byrack_Enable_IMM24_02 "绝缘采样使能位_IMM24";
CM_ SG_ 2332113042 M2I_Byrack_ReVeEnable_IMM24_02 "读取软件版本使能位_IMM24";
CM_ SG_ 2332113042 Reserved_02 "预留预留";
CM_ SG_ 2332113042 M2I_Byrack_IsPostTm_IMM24_02 "绝缘采样时间_IMM24";
CM_ SG_ 2332113042 M2I_Byrack_SysABStTm_IMM24_02 "电压稳定时间_IMM24";
CM_ SG_ 2332113043 CRC_M2I_Byrack_IMM24_03 "CRC校验_IMM24";
CM_ SG_ 2332113043 M2I_Byrack_HVS_IMM24_03 "绝缘测量电压_IMM24";
CM_ SG_ 2332113043 M2I_Byrack_Enable_IMM24_03 "绝缘采样使能位_IMM24";
CM_ SG_ 2332113043 M2I_Byrack_ReVeEnable_IMM24_03 "读取软件版本使能位_IMM24";
CM_ SG_ 2332113043 Reserved_03 "预留预留";
CM_ SG_ 2332113043 M2I_Byrack_IsPostTm_IMM24_03 "绝缘采样时间_IMM24";
CM_ SG_ 2332113043 M2I_Byrack_SysABStTm_IMM24_03 "电压稳定时间_IMM24";
CM_ SG_ 2332113044 CRC_M2I_Byrack_IMM24_04 "CRC校验_IMM24";
CM_ SG_ 2332113044 M2I_Byrack_HVS_IMM24_04 "绝缘测量电压_IMM24";
CM_ SG_ 2332113044 M2I_Byrack_Enable_IMM24_04 "绝缘采样使能位_IMM24";
CM_ SG_ 2332113044 M2I_Byrack_ReVeEnable_IMM24_04 "读取软件版本使能位_IMM24";
CM_ SG_ 2332113044 Reserved_04 "预留预留";
CM_ SG_ 2332113044 M2I_Byrack_IsPostTm_IMM24_04 "绝缘采样时间_IMM24";
CM_ SG_ 2332113044 M2I_Byrack_SysABStTm_IMM24_04 "电压稳定时间_IMM24";
CM_ SG_ 2332113045 CRC_M2I_Byrack_IMM24_05 "CRC校验_IMM24";
CM_ SG_ 2332113045 M2I_Byrack_HVS_IMM24_05 "绝缘测量电压_IMM24";
CM_ SG_ 2332113045 M2I_Byrack_Enable_IMM24_05 "绝缘采样使能位_IMM24";
CM_ SG_ 2332113045 M2I_Byrack_ReVeEnable_IMM24_05 "读取软件版本使能位_IMM24";
CM_ SG_ 2332113045 Reserved_05 "预留预留";
CM_ SG_ 2332113045 M2I_Byrack_IsPostTm_IMM24_05 "绝缘采样时间_IMM24";
CM_ SG_ 2332113045 M2I_Byrack_SysABStTm_IMM24_05 "电压稳定时间_IMM24";
CM_ SG_ 2332113046 CRC_M2I_Byrack_IMM24_06 "CRC校验_IMM24";
CM_ SG_ 2332113046 M2I_Byrack_HVS_IMM24_06 "绝缘测量电压_IMM24";
CM_ SG_ 2332113046 M2I_Byrack_Enable_IMM24_06 "绝缘采样使能位_IMM24";
CM_ SG_ 2332113046 M2I_Byrack_ReVeEnable_IMM24_06 "读取软件版本使能位_IMM24";
CM_ SG_ 2332113046 Reserved_06 "预留预留";
CM_ SG_ 2332113046 M2I_Byrack_IsPostTm_IMM24_06 "绝缘采样时间_IMM24";
CM_ SG_ 2332113046 M2I_Byrack_SysABStTm_IMM24_06 "电压稳定时间_IMM24";
CM_ SG_ 2332113047 CRC_M2I_Byrack_IMM24_07 "CRC校验_IMM24";
CM_ SG_ 2332113047 M2I_Byrack_HVS_IMM24_07 "绝缘测量电压_IMM24";
CM_ SG_ 2332113047 M2I_Byrack_Enable_IMM24_07 "绝缘采样使能位_IMM24";
CM_ SG_ 2332113047 M2I_Byrack_ReVeEnable_IMM24_07 "读取软件版本使能位_IMM24";
CM_ SG_ 2332113047 Reserved_07 "预留预留";
CM_ SG_ 2332113047 M2I_Byrack_IsPostTm_IMM24_07 "绝缘采样时间_IMM24";
CM_ SG_ 2332113047 M2I_Byrack_SysABStTm_IMM24_07 "电压稳定时间_IMM24";
CM_ SG_ 2332113048 CRC_M2I_Byrack_IMM24_08 "CRC校验_IMM24";
CM_ SG_ 2332113048 M2I_Byrack_HVS_IMM24_08 "绝缘测量电压_IMM24";
CM_ SG_ 2332113048 M2I_Byrack_Enable_IMM24_08 "绝缘采样使能位_IMM24";
CM_ SG_ 2332113048 M2I_Byrack_ReVeEnable_IMM24_08 "读取软件版本使能位_IMM24";
CM_ SG_ 2332113048 Reserved_08 "预留预留";
CM_ SG_ 2332113048 M2I_Byrack_IsPostTm_IMM24_08 "绝缘采样时间_IMM24";
CM_ SG_ 2332113048 M2I_Byrack_SysABStTm_IMM24_08 "电压稳定时间_IMM24";
CM_ SG_ 2332113049 CRC_M2I_Byrack_IMM24_09 "CRC校验_IMM24";
CM_ SG_ 2332113049 M2I_Byrack_HVS_IMM24_09 "绝缘测量电压_IMM24";
CM_ SG_ 2332113049 M2I_Byrack_Enable_IMM24_09 "绝缘采样使能位_IMM24";
CM_ SG_ 2332113049 M2I_Byrack_ReVeEnable_IMM24_09 "读取软件版本使能位_IMM24";
CM_ SG_ 2332113049 Reserved_09 "预留预留";
CM_ SG_ 2332113049 M2I_Byrack_IsPostTm_IMM24_09 "绝缘采样时间_IMM24";
CM_ SG_ 2332113049 M2I_Byrack_SysABStTm_IMM24_09 "电压稳定时间_IMM24";
CM_ SG_ 2332113050 CRC_M2I_Byrack_IMM24_10 "CRC校验_IMM24";
CM_ SG_ 2332113050 M2I_Byrack_HVS_IMM24_10 "绝缘测量电压_IMM24";
CM_ SG_ 2332113050 M2I_Byrack_Enable_IMM24_10 "绝缘采样使能位_IMM24";
CM_ SG_ 2332113050 M2I_Byrack_ReVeEnable_IMM24_10 "读取软件版本使能位_IMM24";
CM_ SG_ 2332113050 Reserved_10 "预留预留";
CM_ SG_ 2332113050 M2I_Byrack_IsPostTm_IMM24_10 "绝缘采样时间_IMM24";
CM_ SG_ 2332113050 M2I_Byrack_SysABStTm_IMM24_10 "电压稳定时间_IMM24";
CM_ SG_ 2332113051 CRC_M2I_Byrack_IMM24_11 "CRC校验_IMM24";
CM_ SG_ 2332113051 M2I_Byrack_HVS_IMM24_11 "绝缘测量电压_IMM24";
CM_ SG_ 2332113051 M2I_Byrack_Enable_IMM24_11 "绝缘采样使能位_IMM24";
CM_ SG_ 2332113051 M2I_Byrack_ReVeEnable_IMM24_11 "读取软件版本使能位_IMM24";
CM_ SG_ 2332113051 Reserved_11 "预留预留";
CM_ SG_ 2332113051 M2I_Byrack_IsPostTm_IMM24_11 "绝缘采样时间_IMM24";
CM_ SG_ 2332113051 M2I_Byrack_SysABStTm_IMM24_11 "电压稳定时间_IMM24";
CM_ SG_ 2332113052 CRC_M2I_Byrack_IMM24_12 "CRC校验_IMM24";
CM_ SG_ 2332113052 M2I_Byrack_HVS_IMM24_12 "绝缘测量电压_IMM24";
CM_ SG_ 2332113052 M2I_Byrack_Enable_IMM24_12 "绝缘采样使能位_IMM24";
CM_ SG_ 2332113052 M2I_Byrack_ReVeEnable_IMM24_12 "读取软件版本使能位_IMM24";
CM_ SG_ 2332113052 Reserved_12 "预留预留";
CM_ SG_ 2332113052 M2I_Byrack_IsPostTm_IMM24_12 "绝缘采样时间_IMM24";
CM_ SG_ 2332113052 M2I_Byrack_SysABStTm_IMM24_12 "电压稳定时间_IMM24";
CM_ SG_ 2332113053 CRC_M2I_Byrack_IMM24_13 "CRC校验_IMM24";
CM_ SG_ 2332113053 M2I_Byrack_HVS_IMM24_13 "绝缘测量电压_IMM24";
CM_ SG_ 2332113053 M2I_Byrack_Enable_IMM24_13 "绝缘采样使能位_IMM24";
CM_ SG_ 2332113053 M2I_Byrack_ReVeEnable_IMM24_13 "读取软件版本使能位_IMM24";
CM_ SG_ 2332113053 Reserved_13 "预留预留";
CM_ SG_ 2332113053 M2I_Byrack_IsPostTm_IMM24_13 "绝缘采样时间_IMM24";
CM_ SG_ 2332113053 M2I_Byrack_SysABStTm_IMM24_13 "电压稳定时间_IMM24";
CM_ SG_ 2332113054 CRC_M2I_Byrack_IMM24_14 "CRC校验_IMM24";
CM_ SG_ 2332113054 M2I_Byrack_HVS_IMM24_14 "绝缘测量电压_IMM24";
CM_ SG_ 2332113054 M2I_Byrack_Enable_IMM24_14 "绝缘采样使能位_IMM24";
CM_ SG_ 2332113054 M2I_Byrack_ReVeEnable_IMM24_14 "读取软件版本使能位_IMM24";
CM_ SG_ 2332113054 Reserved_14 "预留预留";
CM_ SG_ 2332113054 M2I_Byrack_IsPostTm_IMM24_14 "绝缘采样时间_IMM24";
CM_ SG_ 2332113054 M2I_Byrack_SysABStTm_IMM24_14 "电压稳定时间_IMM24";
CM_ SG_ 2332113055 CRC_M2I_Byrack_IMM24_15 "CRC校验_IMM24";
CM_ SG_ 2332113055 M2I_Byrack_HVS_IMM24_15 "绝缘测量电压_IMM24";
CM_ SG_ 2332113055 M2I_Byrack_Enable_IMM24_15 "绝缘采样使能位_IMM24";
CM_ SG_ 2332113055 M2I_Byrack_ReVeEnable_IMM24_15 "读取软件版本使能位_IMM24";
CM_ SG_ 2332113055 Reserved_15 "预留预留";
CM_ SG_ 2332113055 M2I_Byrack_IsPostTm_IMM24_15 "绝缘采样时间_IMM24";
CM_ SG_ 2332113055 M2I_Byrack_SysABStTm_IMM24_15 "电压稳定时间_IMM24";
CM_ SG_ 2332113056 CRC_M2I_Byrack_IMM24_16 "CRC校验_IMM24";
CM_ SG_ 2332113056 M2I_Byrack_HVS_IMM24_16 "绝缘测量电压_IMM24";
CM_ SG_ 2332113056 M2I_Byrack_Enable_IMM24_16 "绝缘采样使能位_IMM24";
CM_ SG_ 2332113056 M2I_Byrack_ReVeEnable_IMM24_16 "读取软件版本使能位_IMM24";
CM_ SG_ 2332113056 Reserved_16 "预留预留";
CM_ SG_ 2332113056 M2I_Byrack_IsPostTm_IMM24_16 "绝缘采样时间_IMM24";
CM_ SG_ 2332113056 M2I_Byrack_SysABStTm_IMM24_16 "电压稳定时间_IMM24";
CM_ SG_ 2332113057 CRC_M2I_Byrack_IMM24_17 "CRC校验_IMM24";
CM_ SG_ 2332113057 M2I_Byrack_HVS_IMM24_17 "绝缘测量电压_IMM24";
CM_ SG_ 2332113057 M2I_Byrack_Enable_IMM24_17 "绝缘采样使能位_IMM24";
CM_ SG_ 2332113057 M2I_Byrack_ReVeEnable_IMM24_17 "读取软件版本使能位_IMM24";
CM_ SG_ 2332113057 Reserved_17 "预留预留";
CM_ SG_ 2332113057 M2I_Byrack_IsPostTm_IMM24_17 "绝缘采样时间_IMM24";
CM_ SG_ 2332113057 M2I_Byrack_SysABStTm_IMM24_17 "电压稳定时间_IMM24";
CM_ SG_ 2332113058 CRC_M2I_Byrack_IMM24_18 "CRC校验_IMM24";
CM_ SG_ 2332113058 M2I_Byrack_HVS_IMM24_18 "绝缘测量电压_IMM24";
CM_ SG_ 2332113058 M2I_Byrack_Enable_IMM24_18 "绝缘采样使能位_IMM24";
CM_ SG_ 2332113058 M2I_Byrack_ReVeEnable_IMM24_18 "读取软件版本使能位_IMM24";
CM_ SG_ 2332113058 Reserved_18 "预留预留";
CM_ SG_ 2332113058 M2I_Byrack_IsPostTm_IMM24_18 "绝缘采样时间_IMM24";
CM_ SG_ 2332113058 M2I_Byrack_SysABStTm_IMM24_18 "电压稳定时间_IMM24";
CM_ SG_ 2332113059 CRC_M2I_Byrack_IMM24_19 "CRC校验_IMM24";
CM_ SG_ 2332113059 M2I_Byrack_HVS_IMM24_19 "绝缘测量电压_IMM24";
CM_ SG_ 2332113059 M2I_Byrack_Enable_IMM24_19 "绝缘采样使能位_IMM24";
CM_ SG_ 2332113059 M2I_Byrack_ReVeEnable_IMM24_19 "读取软件版本使能位_IMM24";
CM_ SG_ 2332113059 Reserved_19 "预留预留";
CM_ SG_ 2332113059 M2I_Byrack_IsPostTm_IMM24_19 "绝缘采样时间_IMM24";
CM_ SG_ 2332113059 M2I_Byrack_SysABStTm_IMM24_19 "电压稳定时间_IMM24";
CM_ SG_ 2332113060 CRC_M2I_Byrack_IMM24_20 "CRC校验_IMM24";
CM_ SG_ 2332113060 M2I_Byrack_HVS_IMM24_20 "绝缘测量电压_IMM24";
CM_ SG_ 2332113060 M2I_Byrack_Enable_IMM24_20 "绝缘采样使能位_IMM24";
CM_ SG_ 2332113060 M2I_Byrack_ReVeEnable_IMM24_20 "读取软件版本使能位_IMM24";
CM_ SG_ 2332113060 Reserved_20 "预留预留";
CM_ SG_ 2332113060 M2I_Byrack_IsPostTm_IMM24_20 "绝缘采样时间_IMM24";
CM_ SG_ 2332113060 M2I_Byrack_SysABStTm_IMM24_20 "电压稳定时间_IMM24";
CM_ SG_ 2332113061 CRC_M2I_Byrack_IMM24_21 "CRC校验_IMM24";
CM_ SG_ 2332113061 M2I_Byrack_HVS_IMM24_21 "绝缘测量电压_IMM24";
CM_ SG_ 2332113061 M2I_Byrack_Enable_IMM24_21 "绝缘采样使能位_IMM24";
CM_ SG_ 2332113061 M2I_Byrack_ReVeEnable_IMM24_21 "读取软件版本使能位_IMM24";
CM_ SG_ 2332113061 Reserved_21 "预留预留";
CM_ SG_ 2332113061 M2I_Byrack_IsPostTm_IMM24_21 "绝缘采样时间_IMM24";
CM_ SG_ 2332113061 M2I_Byrack_SysABStTm_IMM24_21 "电压稳定时间_IMM24";
CM_ SG_ 2332113062 CRC_M2I_Byrack_IMM24_22 "CRC校验_IMM24";
CM_ SG_ 2332113062 M2I_Byrack_HVS_IMM24_22 "绝缘测量电压_IMM24";
CM_ SG_ 2332113062 M2I_Byrack_Enable_IMM24_22 "绝缘采样使能位_IMM24";
CM_ SG_ 2332113062 M2I_Byrack_ReVeEnable_IMM24_22 "读取软件版本使能位_IMM24";
CM_ SG_ 2332113062 Reserved_22 "预留预留";
CM_ SG_ 2332113062 M2I_Byrack_IsPostTm_IMM24_22 "绝缘采样时间_IMM24";
CM_ SG_ 2332113062 M2I_Byrack_SysABStTm_IMM24_22 "电压稳定时间_IMM24";
CM_ SG_ 2332113063 CRC_M2I_Byrack_IMM24_23 "CRC校验_IMM24";
CM_ SG_ 2332113063 M2I_Byrack_HVS_IMM24_23 "绝缘测量电压_IMM24";
CM_ SG_ 2332113063 M2I_Byrack_Enable_IMM24_23 "绝缘采样使能位_IMM24";
CM_ SG_ 2332113063 M2I_Byrack_ReVeEnable_IMM24_23 "读取软件版本使能位_IMM24";
CM_ SG_ 2332113063 Reserved_23 "预留预留";
CM_ SG_ 2332113063 M2I_Byrack_IsPostTm_IMM24_23 "绝缘采样时间_IMM24";
CM_ SG_ 2332113063 M2I_Byrack_SysABStTm_IMM24_23 "电压稳定时间_IMM24";
CM_ SG_ 2332113064 CRC_M2I_Byrack_IMM24_24 "CRC校验_IMM24";
CM_ SG_ 2332113064 M2I_Byrack_HVS_IMM24_24 "绝缘测量电压_IMM24";
CM_ SG_ 2332113064 M2I_Byrack_Enable_IMM24_24 "绝缘采样使能位_IMM24";
CM_ SG_ 2332113064 M2I_Byrack_ReVeEnable_IMM24_24 "读取软件版本使能位_IMM24";
CM_ SG_ 2332113064 Reserved_24 "预留预留";
CM_ SG_ 2332113064 M2I_Byrack_IsPostTm_IMM24_24 "绝缘采样时间_IMM24";
CM_ SG_ 2332113064 M2I_Byrack_SysABStTm_IMM24_24 "电压稳定时间_IMM24";
CM_ SG_ 2332113065 CRC_M2I_Byrack_IMM24_25 "CRC校验_IMM24";
CM_ SG_ 2332113065 M2I_Byrack_HVS_IMM24_25 "绝缘测量电压_IMM24";
CM_ SG_ 2332113065 M2I_Byrack_Enable_IMM24_25 "绝缘采样使能位_IMM24";
CM_ SG_ 2332113065 M2I_Byrack_ReVeEnable_IMM24_25 "读取软件版本使能位_IMM24";
CM_ SG_ 2332113065 Reserved_25 "预留预留";
CM_ SG_ 2332113065 M2I_Byrack_IsPostTm_IMM24_25 "绝缘采样时间_IMM24";
CM_ SG_ 2332113065 M2I_Byrack_SysABStTm_IMM24_25 "电压稳定时间_IMM24";
CM_ SG_ 2332113066 CRC_M2I_Byrack_IMM24_26 "CRC校验_IMM24";
CM_ SG_ 2332113066 M2I_Byrack_HVS_IMM24_26 "绝缘测量电压_IMM24";
CM_ SG_ 2332113066 M2I_Byrack_Enable_IMM24_26 "绝缘采样使能位_IMM24";
CM_ SG_ 2332113066 M2I_Byrack_ReVeEnable_IMM24_26 "读取软件版本使能位_IMM24";
CM_ SG_ 2332113066 Reserved_26 "预留预留";
CM_ SG_ 2332113066 M2I_Byrack_IsPostTm_IMM24_26 "绝缘采样时间_IMM24";
CM_ SG_ 2332113066 M2I_Byrack_SysABStTm_IMM24_26 "电压稳定时间_IMM24";
CM_ SG_ 2332113067 CRC_M2I_Byrack_IMM24_27 "CRC校验_IMM24";
CM_ SG_ 2332113067 M2I_Byrack_HVS_IMM24_27 "绝缘测量电压_IMM24";
CM_ SG_ 2332113067 M2I_Byrack_Enable_IMM24_27 "绝缘采样使能位_IMM24";
CM_ SG_ 2332113067 M2I_Byrack_ReVeEnable_IMM24_27 "读取软件版本使能位_IMM24";
CM_ SG_ 2332113067 Reserved_27 "预留预留";
CM_ SG_ 2332113067 M2I_Byrack_IsPostTm_IMM24_27 "绝缘采样时间_IMM24";
CM_ SG_ 2332113067 M2I_Byrack_SysABStTm_IMM24_27 "电压稳定时间_IMM24";
CM_ SG_ 2332113068 CRC_M2I_Byrack_IMM24_28 "CRC校验_IMM24";
CM_ SG_ 2332113068 M2I_Byrack_HVS_IMM24_28 "绝缘测量电压_IMM24";
CM_ SG_ 2332113068 M2I_Byrack_Enable_IMM24_28 "绝缘采样使能位_IMM24";
CM_ SG_ 2332113068 M2I_Byrack_ReVeEnable_IMM24_28 "读取软件版本使能位_IMM24";
CM_ SG_ 2332113068 Reserved_28 "预留预留";
CM_ SG_ 2332113068 M2I_Byrack_IsPostTm_IMM24_28 "绝缘采样时间_IMM24";
CM_ SG_ 2332113068 M2I_Byrack_SysABStTm_IMM24_28 "电压稳定时间_IMM24";
CM_ SG_ 2332113069 CRC_M2I_Byrack_IMM24_29 "CRC校验_IMM24";
CM_ SG_ 2332113069 M2I_Byrack_HVS_IMM24_29 "绝缘测量电压_IMM24";
CM_ SG_ 2332113069 M2I_Byrack_Enable_IMM24_29 "绝缘采样使能位_IMM24";
CM_ SG_ 2332113069 M2I_Byrack_ReVeEnable_IMM24_29 "读取软件版本使能位_IMM24";
CM_ SG_ 2332113069 Reserved_29 "预留预留";
CM_ SG_ 2332113069 M2I_Byrack_IsPostTm_IMM24_29 "绝缘采样时间_IMM24";
CM_ SG_ 2332113069 M2I_Byrack_SysABStTm_IMM24_29 "电压稳定时间_IMM24";
CM_ SG_ 2332113070 CRC_M2I_Byrack_IMM24_30 "CRC校验_IMM24";
CM_ SG_ 2332113070 M2I_Byrack_HVS_IMM24_30 "绝缘测量电压_IMM24";
CM_ SG_ 2332113070 M2I_Byrack_Enable_IMM24_30 "绝缘采样使能位_IMM24";
CM_ SG_ 2332113070 M2I_Byrack_ReVeEnable_IMM24_30 "读取软件版本使能位_IMM24";
CM_ SG_ 2332113070 Reserved_30 "预留预留";
CM_ SG_ 2332113070 M2I_Byrack_IsPostTm_IMM24_30 "绝缘采样时间_IMM24";
CM_ SG_ 2332113070 M2I_Byrack_SysABStTm_IMM24_30 "电压稳定时间_IMM24";
CM_ SG_ 2332113071 CRC_M2I_Byrack_IMM24_31 "CRC校验_IMM24";
CM_ SG_ 2332113071 M2I_Byrack_HVS_IMM24_31 "绝缘测量电压_IMM24";
CM_ SG_ 2332113071 M2I_Byrack_Enable_IMM24_31 "绝缘采样使能位_IMM24";
CM_ SG_ 2332113071 M2I_Byrack_ReVeEnable_IMM24_31 "读取软件版本使能位_IMM24";
CM_ SG_ 2332113071 Reserved_31 "预留预留";
CM_ SG_ 2332113071 M2I_Byrack_IsPostTm_IMM24_31 "绝缘采样时间_IMM24";
CM_ SG_ 2332113071 M2I_Byrack_SysABStTm_IMM24_31 "电压稳定时间_IMM24";
CM_ SG_ 2332113297 CRC_M2I_Byrack_IMM25_01 "CRC校验_IMM25";
CM_ SG_ 2332113297 M2I_Byrack_HVS_IMM25_01 "绝缘测量电压_IMM25";
CM_ SG_ 2332113297 M2I_Byrack_Enable_IMM25_01 "绝缘采样使能位_IMM25";
CM_ SG_ 2332113297 M2I_Byrack_ReVeEnable_IMM25_01 "读取软件版本使能位_IMM25";
CM_ SG_ 2332113297 Reserved_01 "预留预留";
CM_ SG_ 2332113297 M2I_Byrack_IsPostTm_IMM25_01 "绝缘采样时间_IMM25";
CM_ SG_ 2332113297 M2I_Byrack_SysABStTm_IMM25_01 "电压稳定时间_IMM25";
CM_ SG_ 2332113298 CRC_M2I_Byrack_IMM25_02 "CRC校验_IMM25";
CM_ SG_ 2332113298 M2I_Byrack_HVS_IMM25_02 "绝缘测量电压_IMM25";
CM_ SG_ 2332113298 M2I_Byrack_Enable_IMM25_02 "绝缘采样使能位_IMM25";
CM_ SG_ 2332113298 M2I_Byrack_ReVeEnable_IMM25_02 "读取软件版本使能位_IMM25";
CM_ SG_ 2332113298 Reserved_02 "预留预留";
CM_ SG_ 2332113298 M2I_Byrack_IsPostTm_IMM25_02 "绝缘采样时间_IMM25";
CM_ SG_ 2332113298 M2I_Byrack_SysABStTm_IMM25_02 "电压稳定时间_IMM25";
CM_ SG_ 2332113299 CRC_M2I_Byrack_IMM25_03 "CRC校验_IMM25";
CM_ SG_ 2332113299 M2I_Byrack_HVS_IMM25_03 "绝缘测量电压_IMM25";
CM_ SG_ 2332113299 M2I_Byrack_Enable_IMM25_03 "绝缘采样使能位_IMM25";
CM_ SG_ 2332113299 M2I_Byrack_ReVeEnable_IMM25_03 "读取软件版本使能位_IMM25";
CM_ SG_ 2332113299 Reserved_03 "预留预留";
CM_ SG_ 2332113299 M2I_Byrack_IsPostTm_IMM25_03 "绝缘采样时间_IMM25";
CM_ SG_ 2332113299 M2I_Byrack_SysABStTm_IMM25_03 "电压稳定时间_IMM25";
CM_ SG_ 2332113300 CRC_M2I_Byrack_IMM25_04 "CRC校验_IMM25";
CM_ SG_ 2332113300 M2I_Byrack_HVS_IMM25_04 "绝缘测量电压_IMM25";
CM_ SG_ 2332113300 M2I_Byrack_Enable_IMM25_04 "绝缘采样使能位_IMM25";
CM_ SG_ 2332113300 M2I_Byrack_ReVeEnable_IMM25_04 "读取软件版本使能位_IMM25";
CM_ SG_ 2332113300 Reserved_04 "预留预留";
CM_ SG_ 2332113300 M2I_Byrack_IsPostTm_IMM25_04 "绝缘采样时间_IMM25";
CM_ SG_ 2332113300 M2I_Byrack_SysABStTm_IMM25_04 "电压稳定时间_IMM25";
CM_ SG_ 2332113301 CRC_M2I_Byrack_IMM25_05 "CRC校验_IMM25";
CM_ SG_ 2332113301 M2I_Byrack_HVS_IMM25_05 "绝缘测量电压_IMM25";
CM_ SG_ 2332113301 M2I_Byrack_Enable_IMM25_05 "绝缘采样使能位_IMM25";
CM_ SG_ 2332113301 M2I_Byrack_ReVeEnable_IMM25_05 "读取软件版本使能位_IMM25";
CM_ SG_ 2332113301 Reserved_05 "预留预留";
CM_ SG_ 2332113301 M2I_Byrack_IsPostTm_IMM25_05 "绝缘采样时间_IMM25";
CM_ SG_ 2332113301 M2I_Byrack_SysABStTm_IMM25_05 "电压稳定时间_IMM25";
CM_ SG_ 2332113302 CRC_M2I_Byrack_IMM25_06 "CRC校验_IMM25";
CM_ SG_ 2332113302 M2I_Byrack_HVS_IMM25_06 "绝缘测量电压_IMM25";
CM_ SG_ 2332113302 M2I_Byrack_Enable_IMM25_06 "绝缘采样使能位_IMM25";
CM_ SG_ 2332113302 M2I_Byrack_ReVeEnable_IMM25_06 "读取软件版本使能位_IMM25";
CM_ SG_ 2332113302 Reserved_06 "预留预留";
CM_ SG_ 2332113302 M2I_Byrack_IsPostTm_IMM25_06 "绝缘采样时间_IMM25";
CM_ SG_ 2332113302 M2I_Byrack_SysABStTm_IMM25_06 "电压稳定时间_IMM25";
CM_ SG_ 2332113303 CRC_M2I_Byrack_IMM25_07 "CRC校验_IMM25";
CM_ SG_ 2332113303 M2I_Byrack_HVS_IMM25_07 "绝缘测量电压_IMM25";
CM_ SG_ 2332113303 M2I_Byrack_Enable_IMM25_07 "绝缘采样使能位_IMM25";
CM_ SG_ 2332113303 M2I_Byrack_ReVeEnable_IMM25_07 "读取软件版本使能位_IMM25";
CM_ SG_ 2332113303 Reserved_07 "预留预留";
CM_ SG_ 2332113303 M2I_Byrack_IsPostTm_IMM25_07 "绝缘采样时间_IMM25";
CM_ SG_ 2332113303 M2I_Byrack_SysABStTm_IMM25_07 "电压稳定时间_IMM25";
CM_ SG_ 2332113304 CRC_M2I_Byrack_IMM25_08 "CRC校验_IMM25";
CM_ SG_ 2332113304 M2I_Byrack_HVS_IMM25_08 "绝缘测量电压_IMM25";
CM_ SG_ 2332113304 M2I_Byrack_Enable_IMM25_08 "绝缘采样使能位_IMM25";
CM_ SG_ 2332113304 M2I_Byrack_ReVeEnable_IMM25_08 "读取软件版本使能位_IMM25";
CM_ SG_ 2332113304 Reserved_08 "预留预留";
CM_ SG_ 2332113304 M2I_Byrack_IsPostTm_IMM25_08 "绝缘采样时间_IMM25";
CM_ SG_ 2332113304 M2I_Byrack_SysABStTm_IMM25_08 "电压稳定时间_IMM25";
CM_ SG_ 2332113305 CRC_M2I_Byrack_IMM25_09 "CRC校验_IMM25";
CM_ SG_ 2332113305 M2I_Byrack_HVS_IMM25_09 "绝缘测量电压_IMM25";
CM_ SG_ 2332113305 M2I_Byrack_Enable_IMM25_09 "绝缘采样使能位_IMM25";
CM_ SG_ 2332113305 M2I_Byrack_ReVeEnable_IMM25_09 "读取软件版本使能位_IMM25";
CM_ SG_ 2332113305 Reserved_09 "预留预留";
CM_ SG_ 2332113305 M2I_Byrack_IsPostTm_IMM25_09 "绝缘采样时间_IMM25";
CM_ SG_ 2332113305 M2I_Byrack_SysABStTm_IMM25_09 "电压稳定时间_IMM25";
CM_ SG_ 2332113306 CRC_M2I_Byrack_IMM25_10 "CRC校验_IMM25";
CM_ SG_ 2332113306 M2I_Byrack_HVS_IMM25_10 "绝缘测量电压_IMM25";
CM_ SG_ 2332113306 M2I_Byrack_Enable_IMM25_10 "绝缘采样使能位_IMM25";
CM_ SG_ 2332113306 M2I_Byrack_ReVeEnable_IMM25_10 "读取软件版本使能位_IMM25";
CM_ SG_ 2332113306 Reserved_10 "预留预留";
CM_ SG_ 2332113306 M2I_Byrack_IsPostTm_IMM25_10 "绝缘采样时间_IMM25";
CM_ SG_ 2332113306 M2I_Byrack_SysABStTm_IMM25_10 "电压稳定时间_IMM25";
CM_ SG_ 2332113307 CRC_M2I_Byrack_IMM25_11 "CRC校验_IMM25";
CM_ SG_ 2332113307 M2I_Byrack_HVS_IMM25_11 "绝缘测量电压_IMM25";
CM_ SG_ 2332113307 M2I_Byrack_Enable_IMM25_11 "绝缘采样使能位_IMM25";
CM_ SG_ 2332113307 M2I_Byrack_ReVeEnable_IMM25_11 "读取软件版本使能位_IMM25";
CM_ SG_ 2332113307 Reserved_11 "预留预留";
CM_ SG_ 2332113307 M2I_Byrack_IsPostTm_IMM25_11 "绝缘采样时间_IMM25";
CM_ SG_ 2332113307 M2I_Byrack_SysABStTm_IMM25_11 "电压稳定时间_IMM25";
CM_ SG_ 2332113308 CRC_M2I_Byrack_IMM25_12 "CRC校验_IMM25";
CM_ SG_ 2332113308 M2I_Byrack_HVS_IMM25_12 "绝缘测量电压_IMM25";
CM_ SG_ 2332113308 M2I_Byrack_Enable_IMM25_12 "绝缘采样使能位_IMM25";
CM_ SG_ 2332113308 M2I_Byrack_ReVeEnable_IMM25_12 "读取软件版本使能位_IMM25";
CM_ SG_ 2332113308 Reserved_12 "预留预留";
CM_ SG_ 2332113308 M2I_Byrack_IsPostTm_IMM25_12 "绝缘采样时间_IMM25";
CM_ SG_ 2332113308 M2I_Byrack_SysABStTm_IMM25_12 "电压稳定时间_IMM25";
CM_ SG_ 2332113309 CRC_M2I_Byrack_IMM25_13 "CRC校验_IMM25";
CM_ SG_ 2332113309 M2I_Byrack_HVS_IMM25_13 "绝缘测量电压_IMM25";
CM_ SG_ 2332113309 M2I_Byrack_Enable_IMM25_13 "绝缘采样使能位_IMM25";
CM_ SG_ 2332113309 M2I_Byrack_ReVeEnable_IMM25_13 "读取软件版本使能位_IMM25";
CM_ SG_ 2332113309 Reserved_13 "预留预留";
CM_ SG_ 2332113309 M2I_Byrack_IsPostTm_IMM25_13 "绝缘采样时间_IMM25";
CM_ SG_ 2332113309 M2I_Byrack_SysABStTm_IMM25_13 "电压稳定时间_IMM25";
CM_ SG_ 2332113310 CRC_M2I_Byrack_IMM25_14 "CRC校验_IMM25";
CM_ SG_ 2332113310 M2I_Byrack_HVS_IMM25_14 "绝缘测量电压_IMM25";
CM_ SG_ 2332113310 M2I_Byrack_Enable_IMM25_14 "绝缘采样使能位_IMM25";
CM_ SG_ 2332113310 M2I_Byrack_ReVeEnable_IMM25_14 "读取软件版本使能位_IMM25";
CM_ SG_ 2332113310 Reserved_14 "预留预留";
CM_ SG_ 2332113310 M2I_Byrack_IsPostTm_IMM25_14 "绝缘采样时间_IMM25";
CM_ SG_ 2332113310 M2I_Byrack_SysABStTm_IMM25_14 "电压稳定时间_IMM25";
CM_ SG_ 2332113311 CRC_M2I_Byrack_IMM25_15 "CRC校验_IMM25";
CM_ SG_ 2332113311 M2I_Byrack_HVS_IMM25_15 "绝缘测量电压_IMM25";
CM_ SG_ 2332113311 M2I_Byrack_Enable_IMM25_15 "绝缘采样使能位_IMM25";
CM_ SG_ 2332113311 M2I_Byrack_ReVeEnable_IMM25_15 "读取软件版本使能位_IMM25";
CM_ SG_ 2332113311 Reserved_15 "预留预留";
CM_ SG_ 2332113311 M2I_Byrack_IsPostTm_IMM25_15 "绝缘采样时间_IMM25";
CM_ SG_ 2332113311 M2I_Byrack_SysABStTm_IMM25_15 "电压稳定时间_IMM25";
CM_ SG_ 2332113312 CRC_M2I_Byrack_IMM25_16 "CRC校验_IMM25";
CM_ SG_ 2332113312 M2I_Byrack_HVS_IMM25_16 "绝缘测量电压_IMM25";
CM_ SG_ 2332113312 M2I_Byrack_Enable_IMM25_16 "绝缘采样使能位_IMM25";
CM_ SG_ 2332113312 M2I_Byrack_ReVeEnable_IMM25_16 "读取软件版本使能位_IMM25";
CM_ SG_ 2332113312 Reserved_16 "预留预留";
CM_ SG_ 2332113312 M2I_Byrack_IsPostTm_IMM25_16 "绝缘采样时间_IMM25";
CM_ SG_ 2332113312 M2I_Byrack_SysABStTm_IMM25_16 "电压稳定时间_IMM25";
CM_ SG_ 2332113313 CRC_M2I_Byrack_IMM25_17 "CRC校验_IMM25";
CM_ SG_ 2332113313 M2I_Byrack_HVS_IMM25_17 "绝缘测量电压_IMM25";
CM_ SG_ 2332113313 M2I_Byrack_Enable_IMM25_17 "绝缘采样使能位_IMM25";
CM_ SG_ 2332113313 M2I_Byrack_ReVeEnable_IMM25_17 "读取软件版本使能位_IMM25";
CM_ SG_ 2332113313 Reserved_17 "预留预留";
CM_ SG_ 2332113313 M2I_Byrack_IsPostTm_IMM25_17 "绝缘采样时间_IMM25";
CM_ SG_ 2332113313 M2I_Byrack_SysABStTm_IMM25_17 "电压稳定时间_IMM25";
CM_ SG_ 2332113314 CRC_M2I_Byrack_IMM25_18 "CRC校验_IMM25";
CM_ SG_ 2332113314 M2I_Byrack_HVS_IMM25_18 "绝缘测量电压_IMM25";
CM_ SG_ 2332113314 M2I_Byrack_Enable_IMM25_18 "绝缘采样使能位_IMM25";
CM_ SG_ 2332113314 M2I_Byrack_ReVeEnable_IMM25_18 "读取软件版本使能位_IMM25";
CM_ SG_ 2332113314 Reserved_18 "预留预留";
CM_ SG_ 2332113314 M2I_Byrack_IsPostTm_IMM25_18 "绝缘采样时间_IMM25";
CM_ SG_ 2332113314 M2I_Byrack_SysABStTm_IMM25_18 "电压稳定时间_IMM25";
CM_ SG_ 2332113315 CRC_M2I_Byrack_IMM25_19 "CRC校验_IMM25";
CM_ SG_ 2332113315 M2I_Byrack_HVS_IMM25_19 "绝缘测量电压_IMM25";
CM_ SG_ 2332113315 M2I_Byrack_Enable_IMM25_19 "绝缘采样使能位_IMM25";
CM_ SG_ 2332113315 M2I_Byrack_ReVeEnable_IMM25_19 "读取软件版本使能位_IMM25";
CM_ SG_ 2332113315 Reserved_19 "预留预留";
CM_ SG_ 2332113315 M2I_Byrack_IsPostTm_IMM25_19 "绝缘采样时间_IMM25";
CM_ SG_ 2332113315 M2I_Byrack_SysABStTm_IMM25_19 "电压稳定时间_IMM25";
CM_ SG_ 2332113316 CRC_M2I_Byrack_IMM25_20 "CRC校验_IMM25";
CM_ SG_ 2332113316 M2I_Byrack_HVS_IMM25_20 "绝缘测量电压_IMM25";
CM_ SG_ 2332113316 M2I_Byrack_Enable_IMM25_20 "绝缘采样使能位_IMM25";
CM_ SG_ 2332113316 M2I_Byrack_ReVeEnable_IMM25_20 "读取软件版本使能位_IMM25";
CM_ SG_ 2332113316 Reserved_20 "预留预留";
CM_ SG_ 2332113316 M2I_Byrack_IsPostTm_IMM25_20 "绝缘采样时间_IMM25";
CM_ SG_ 2332113316 M2I_Byrack_SysABStTm_IMM25_20 "电压稳定时间_IMM25";
CM_ SG_ 2332113317 CRC_M2I_Byrack_IMM25_21 "CRC校验_IMM25";
CM_ SG_ 2332113317 M2I_Byrack_HVS_IMM25_21 "绝缘测量电压_IMM25";
CM_ SG_ 2332113317 M2I_Byrack_Enable_IMM25_21 "绝缘采样使能位_IMM25";
CM_ SG_ 2332113317 M2I_Byrack_ReVeEnable_IMM25_21 "读取软件版本使能位_IMM25";
CM_ SG_ 2332113317 Reserved_21 "预留预留";
CM_ SG_ 2332113317 M2I_Byrack_IsPostTm_IMM25_21 "绝缘采样时间_IMM25";
CM_ SG_ 2332113317 M2I_Byrack_SysABStTm_IMM25_21 "电压稳定时间_IMM25";
CM_ SG_ 2332113318 CRC_M2I_Byrack_IMM25_22 "CRC校验_IMM25";
CM_ SG_ 2332113318 M2I_Byrack_HVS_IMM25_22 "绝缘测量电压_IMM25";
CM_ SG_ 2332113318 M2I_Byrack_Enable_IMM25_22 "绝缘采样使能位_IMM25";
CM_ SG_ 2332113318 M2I_Byrack_ReVeEnable_IMM25_22 "读取软件版本使能位_IMM25";
CM_ SG_ 2332113318 Reserved_22 "预留预留";
CM_ SG_ 2332113318 M2I_Byrack_IsPostTm_IMM25_22 "绝缘采样时间_IMM25";
CM_ SG_ 2332113318 M2I_Byrack_SysABStTm_IMM25_22 "电压稳定时间_IMM25";
CM_ SG_ 2332113319 CRC_M2I_Byrack_IMM25_23 "CRC校验_IMM25";
CM_ SG_ 2332113319 M2I_Byrack_HVS_IMM25_23 "绝缘测量电压_IMM25";
CM_ SG_ 2332113319 M2I_Byrack_Enable_IMM25_23 "绝缘采样使能位_IMM25";
CM_ SG_ 2332113319 M2I_Byrack_ReVeEnable_IMM25_23 "读取软件版本使能位_IMM25";
CM_ SG_ 2332113319 Reserved_23 "预留预留";
CM_ SG_ 2332113319 M2I_Byrack_IsPostTm_IMM25_23 "绝缘采样时间_IMM25";
CM_ SG_ 2332113319 M2I_Byrack_SysABStTm_IMM25_23 "电压稳定时间_IMM25";
CM_ SG_ 2332113320 CRC_M2I_Byrack_IMM25_24 "CRC校验_IMM25";
CM_ SG_ 2332113320 M2I_Byrack_HVS_IMM25_24 "绝缘测量电压_IMM25";
CM_ SG_ 2332113320 M2I_Byrack_Enable_IMM25_24 "绝缘采样使能位_IMM25";
CM_ SG_ 2332113320 M2I_Byrack_ReVeEnable_IMM25_24 "读取软件版本使能位_IMM25";
CM_ SG_ 2332113320 Reserved_24 "预留预留";
CM_ SG_ 2332113320 M2I_Byrack_IsPostTm_IMM25_24 "绝缘采样时间_IMM25";
CM_ SG_ 2332113320 M2I_Byrack_SysABStTm_IMM25_24 "电压稳定时间_IMM25";
CM_ SG_ 2332113321 CRC_M2I_Byrack_IMM25_25 "CRC校验_IMM25";
CM_ SG_ 2332113321 M2I_Byrack_HVS_IMM25_25 "绝缘测量电压_IMM25";
CM_ SG_ 2332113321 M2I_Byrack_Enable_IMM25_25 "绝缘采样使能位_IMM25";
CM_ SG_ 2332113321 M2I_Byrack_ReVeEnable_IMM25_25 "读取软件版本使能位_IMM25";
CM_ SG_ 2332113321 Reserved_25 "预留预留";
CM_ SG_ 2332113321 M2I_Byrack_IsPostTm_IMM25_25 "绝缘采样时间_IMM25";
CM_ SG_ 2332113321 M2I_Byrack_SysABStTm_IMM25_25 "电压稳定时间_IMM25";
CM_ SG_ 2332113322 CRC_M2I_Byrack_IMM25_26 "CRC校验_IMM25";
CM_ SG_ 2332113322 M2I_Byrack_HVS_IMM25_26 "绝缘测量电压_IMM25";
CM_ SG_ 2332113322 M2I_Byrack_Enable_IMM25_26 "绝缘采样使能位_IMM25";
CM_ SG_ 2332113322 M2I_Byrack_ReVeEnable_IMM25_26 "读取软件版本使能位_IMM25";
CM_ SG_ 2332113322 Reserved_26 "预留预留";
CM_ SG_ 2332113322 M2I_Byrack_IsPostTm_IMM25_26 "绝缘采样时间_IMM25";
CM_ SG_ 2332113322 M2I_Byrack_SysABStTm_IMM25_26 "电压稳定时间_IMM25";
CM_ SG_ 2332113323 CRC_M2I_Byrack_IMM25_27 "CRC校验_IMM25";
CM_ SG_ 2332113323 M2I_Byrack_HVS_IMM25_27 "绝缘测量电压_IMM25";
CM_ SG_ 2332113323 M2I_Byrack_Enable_IMM25_27 "绝缘采样使能位_IMM25";
CM_ SG_ 2332113323 M2I_Byrack_ReVeEnable_IMM25_27 "读取软件版本使能位_IMM25";
CM_ SG_ 2332113323 Reserved_27 "预留预留";
CM_ SG_ 2332113323 M2I_Byrack_IsPostTm_IMM25_27 "绝缘采样时间_IMM25";
CM_ SG_ 2332113323 M2I_Byrack_SysABStTm_IMM25_27 "电压稳定时间_IMM25";
CM_ SG_ 2332113324 CRC_M2I_Byrack_IMM25_28 "CRC校验_IMM25";
CM_ SG_ 2332113324 M2I_Byrack_HVS_IMM25_28 "绝缘测量电压_IMM25";
CM_ SG_ 2332113324 M2I_Byrack_Enable_IMM25_28 "绝缘采样使能位_IMM25";
CM_ SG_ 2332113324 M2I_Byrack_ReVeEnable_IMM25_28 "读取软件版本使能位_IMM25";
CM_ SG_ 2332113324 Reserved_28 "预留预留";
CM_ SG_ 2332113324 M2I_Byrack_IsPostTm_IMM25_28 "绝缘采样时间_IMM25";
CM_ SG_ 2332113324 M2I_Byrack_SysABStTm_IMM25_28 "电压稳定时间_IMM25";
CM_ SG_ 2332113325 CRC_M2I_Byrack_IMM25_29 "CRC校验_IMM25";
CM_ SG_ 2332113325 M2I_Byrack_HVS_IMM25_29 "绝缘测量电压_IMM25";
CM_ SG_ 2332113325 M2I_Byrack_Enable_IMM25_29 "绝缘采样使能位_IMM25";
CM_ SG_ 2332113325 M2I_Byrack_ReVeEnable_IMM25_29 "读取软件版本使能位_IMM25";
CM_ SG_ 2332113325 Reserved_29 "预留预留";
CM_ SG_ 2332113325 M2I_Byrack_IsPostTm_IMM25_29 "绝缘采样时间_IMM25";
CM_ SG_ 2332113325 M2I_Byrack_SysABStTm_IMM25_29 "电压稳定时间_IMM25";
CM_ SG_ 2332113326 CRC_M2I_Byrack_IMM25_30 "CRC校验_IMM25";
CM_ SG_ 2332113326 M2I_Byrack_HVS_IMM25_30 "绝缘测量电压_IMM25";
CM_ SG_ 2332113326 M2I_Byrack_Enable_IMM25_30 "绝缘采样使能位_IMM25";
CM_ SG_ 2332113326 M2I_Byrack_ReVeEnable_IMM25_30 "读取软件版本使能位_IMM25";
CM_ SG_ 2332113326 Reserved_30 "预留预留";
CM_ SG_ 2332113326 M2I_Byrack_IsPostTm_IMM25_30 "绝缘采样时间_IMM25";
CM_ SG_ 2332113326 M2I_Byrack_SysABStTm_IMM25_30 "电压稳定时间_IMM25";
CM_ SG_ 2332113327 CRC_M2I_Byrack_IMM25_31 "CRC校验_IMM25";
CM_ SG_ 2332113327 M2I_Byrack_HVS_IMM25_31 "绝缘测量电压_IMM25";
CM_ SG_ 2332113327 M2I_Byrack_Enable_IMM25_31 "绝缘采样使能位_IMM25";
CM_ SG_ 2332113327 M2I_Byrack_ReVeEnable_IMM25_31 "读取软件版本使能位_IMM25";
CM_ SG_ 2332113327 Reserved_31 "预留预留";
CM_ SG_ 2332113327 M2I_Byrack_IsPostTm_IMM25_31 "绝缘采样时间_IMM25";
CM_ SG_ 2332113327 M2I_Byrack_SysABStTm_IMM25_31 "电压稳定时间_IMM25";
CM_ SG_ 2332113553 CRC_M2I_Byrack_IMM26_01 "CRC校验_IMM26";
CM_ SG_ 2332113553 M2I_Byrack_HVS_IMM26_01 "绝缘测量电压_IMM26";
CM_ SG_ 2332113553 M2I_Byrack_Enable_IMM26_01 "绝缘采样使能位_IMM26";
CM_ SG_ 2332113553 M2I_Byrack_ReVeEnable_IMM26_01 "读取软件版本使能位_IMM26";
CM_ SG_ 2332113553 Reserved_01 "预留预留";
CM_ SG_ 2332113553 M2I_Byrack_IsPostTm_IMM26_01 "绝缘采样时间_IMM26";
CM_ SG_ 2332113553 M2I_Byrack_SysABStTm_IMM26_01 "电压稳定时间_IMM26";
CM_ SG_ 2332113554 CRC_M2I_Byrack_IMM26_02 "CRC校验_IMM26";
CM_ SG_ 2332113554 M2I_Byrack_HVS_IMM26_02 "绝缘测量电压_IMM26";
CM_ SG_ 2332113554 M2I_Byrack_Enable_IMM26_02 "绝缘采样使能位_IMM26";
CM_ SG_ 2332113554 M2I_Byrack_ReVeEnable_IMM26_02 "读取软件版本使能位_IMM26";
CM_ SG_ 2332113554 Reserved_02 "预留预留";
CM_ SG_ 2332113554 M2I_Byrack_IsPostTm_IMM26_02 "绝缘采样时间_IMM26";
CM_ SG_ 2332113554 M2I_Byrack_SysABStTm_IMM26_02 "电压稳定时间_IMM26";
CM_ SG_ 2332113555 CRC_M2I_Byrack_IMM26_03 "CRC校验_IMM26";
CM_ SG_ 2332113555 M2I_Byrack_HVS_IMM26_03 "绝缘测量电压_IMM26";
CM_ SG_ 2332113555 M2I_Byrack_Enable_IMM26_03 "绝缘采样使能位_IMM26";
CM_ SG_ 2332113555 M2I_Byrack_ReVeEnable_IMM26_03 "读取软件版本使能位_IMM26";
CM_ SG_ 2332113555 Reserved_03 "预留预留";
CM_ SG_ 2332113555 M2I_Byrack_IsPostTm_IMM26_03 "绝缘采样时间_IMM26";
CM_ SG_ 2332113555 M2I_Byrack_SysABStTm_IMM26_03 "电压稳定时间_IMM26";
CM_ SG_ 2332113556 CRC_M2I_Byrack_IMM26_04 "CRC校验_IMM26";
CM_ SG_ 2332113556 M2I_Byrack_HVS_IMM26_04 "绝缘测量电压_IMM26";
CM_ SG_ 2332113556 M2I_Byrack_Enable_IMM26_04 "绝缘采样使能位_IMM26";
CM_ SG_ 2332113556 M2I_Byrack_ReVeEnable_IMM26_04 "读取软件版本使能位_IMM26";
CM_ SG_ 2332113556 Reserved_04 "预留预留";
CM_ SG_ 2332113556 M2I_Byrack_IsPostTm_IMM26_04 "绝缘采样时间_IMM26";
CM_ SG_ 2332113556 M2I_Byrack_SysABStTm_IMM26_04 "电压稳定时间_IMM26";
CM_ SG_ 2332113557 CRC_M2I_Byrack_IMM26_05 "CRC校验_IMM26";
CM_ SG_ 2332113557 M2I_Byrack_HVS_IMM26_05 "绝缘测量电压_IMM26";
CM_ SG_ 2332113557 M2I_Byrack_Enable_IMM26_05 "绝缘采样使能位_IMM26";
CM_ SG_ 2332113557 M2I_Byrack_ReVeEnable_IMM26_05 "读取软件版本使能位_IMM26";
CM_ SG_ 2332113557 Reserved_05 "预留预留";
CM_ SG_ 2332113557 M2I_Byrack_IsPostTm_IMM26_05 "绝缘采样时间_IMM26";
CM_ SG_ 2332113557 M2I_Byrack_SysABStTm_IMM26_05 "电压稳定时间_IMM26";
CM_ SG_ 2332113558 CRC_M2I_Byrack_IMM26_06 "CRC校验_IMM26";
CM_ SG_ 2332113558 M2I_Byrack_HVS_IMM26_06 "绝缘测量电压_IMM26";
CM_ SG_ 2332113558 M2I_Byrack_Enable_IMM26_06 "绝缘采样使能位_IMM26";
CM_ SG_ 2332113558 M2I_Byrack_ReVeEnable_IMM26_06 "读取软件版本使能位_IMM26";
CM_ SG_ 2332113558 Reserved_06 "预留预留";
CM_ SG_ 2332113558 M2I_Byrack_IsPostTm_IMM26_06 "绝缘采样时间_IMM26";
CM_ SG_ 2332113558 M2I_Byrack_SysABStTm_IMM26_06 "电压稳定时间_IMM26";
CM_ SG_ 2332113559 CRC_M2I_Byrack_IMM26_07 "CRC校验_IMM26";
CM_ SG_ 2332113559 M2I_Byrack_HVS_IMM26_07 "绝缘测量电压_IMM26";
CM_ SG_ 2332113559 M2I_Byrack_Enable_IMM26_07 "绝缘采样使能位_IMM26";
CM_ SG_ 2332113559 M2I_Byrack_ReVeEnable_IMM26_07 "读取软件版本使能位_IMM26";
CM_ SG_ 2332113559 Reserved_07 "预留预留";
CM_ SG_ 2332113559 M2I_Byrack_IsPostTm_IMM26_07 "绝缘采样时间_IMM26";
CM_ SG_ 2332113559 M2I_Byrack_SysABStTm_IMM26_07 "电压稳定时间_IMM26";
CM_ SG_ 2332113560 CRC_M2I_Byrack_IMM26_08 "CRC校验_IMM26";
CM_ SG_ 2332113560 M2I_Byrack_HVS_IMM26_08 "绝缘测量电压_IMM26";
CM_ SG_ 2332113560 M2I_Byrack_Enable_IMM26_08 "绝缘采样使能位_IMM26";
CM_ SG_ 2332113560 M2I_Byrack_ReVeEnable_IMM26_08 "读取软件版本使能位_IMM26";
CM_ SG_ 2332113560 Reserved_08 "预留预留";
CM_ SG_ 2332113560 M2I_Byrack_IsPostTm_IMM26_08 "绝缘采样时间_IMM26";
CM_ SG_ 2332113560 M2I_Byrack_SysABStTm_IMM26_08 "电压稳定时间_IMM26";
CM_ SG_ 2332113561 CRC_M2I_Byrack_IMM26_09 "CRC校验_IMM26";
CM_ SG_ 2332113561 M2I_Byrack_HVS_IMM26_09 "绝缘测量电压_IMM26";
CM_ SG_ 2332113561 M2I_Byrack_Enable_IMM26_09 "绝缘采样使能位_IMM26";
CM_ SG_ 2332113561 M2I_Byrack_ReVeEnable_IMM26_09 "读取软件版本使能位_IMM26";
CM_ SG_ 2332113561 Reserved_09 "预留预留";
CM_ SG_ 2332113561 M2I_Byrack_IsPostTm_IMM26_09 "绝缘采样时间_IMM26";
CM_ SG_ 2332113561 M2I_Byrack_SysABStTm_IMM26_09 "电压稳定时间_IMM26";
CM_ SG_ 2332113562 CRC_M2I_Byrack_IMM26_10 "CRC校验_IMM26";
CM_ SG_ 2332113562 M2I_Byrack_HVS_IMM26_10 "绝缘测量电压_IMM26";
CM_ SG_ 2332113562 M2I_Byrack_Enable_IMM26_10 "绝缘采样使能位_IMM26";
CM_ SG_ 2332113562 M2I_Byrack_ReVeEnable_IMM26_10 "读取软件版本使能位_IMM26";
CM_ SG_ 2332113562 Reserved_10 "预留预留";
CM_ SG_ 2332113562 M2I_Byrack_IsPostTm_IMM26_10 "绝缘采样时间_IMM26";
CM_ SG_ 2332113562 M2I_Byrack_SysABStTm_IMM26_10 "电压稳定时间_IMM26";
CM_ SG_ 2332113563 CRC_M2I_Byrack_IMM26_11 "CRC校验_IMM26";
CM_ SG_ 2332113563 M2I_Byrack_HVS_IMM26_11 "绝缘测量电压_IMM26";
CM_ SG_ 2332113563 M2I_Byrack_Enable_IMM26_11 "绝缘采样使能位_IMM26";
CM_ SG_ 2332113563 M2I_Byrack_ReVeEnable_IMM26_11 "读取软件版本使能位_IMM26";
CM_ SG_ 2332113563 Reserved_11 "预留预留";
CM_ SG_ 2332113563 M2I_Byrack_IsPostTm_IMM26_11 "绝缘采样时间_IMM26";
CM_ SG_ 2332113563 M2I_Byrack_SysABStTm_IMM26_11 "电压稳定时间_IMM26";
CM_ SG_ 2332113564 CRC_M2I_Byrack_IMM26_12 "CRC校验_IMM26";
CM_ SG_ 2332113564 M2I_Byrack_HVS_IMM26_12 "绝缘测量电压_IMM26";
CM_ SG_ 2332113564 M2I_Byrack_Enable_IMM26_12 "绝缘采样使能位_IMM26";
CM_ SG_ 2332113564 M2I_Byrack_ReVeEnable_IMM26_12 "读取软件版本使能位_IMM26";
CM_ SG_ 2332113564 Reserved_12 "预留预留";
CM_ SG_ 2332113564 M2I_Byrack_IsPostTm_IMM26_12 "绝缘采样时间_IMM26";
CM_ SG_ 2332113564 M2I_Byrack_SysABStTm_IMM26_12 "电压稳定时间_IMM26";
CM_ SG_ 2332113565 CRC_M2I_Byrack_IMM26_13 "CRC校验_IMM26";
CM_ SG_ 2332113565 M2I_Byrack_HVS_IMM26_13 "绝缘测量电压_IMM26";
CM_ SG_ 2332113565 M2I_Byrack_Enable_IMM26_13 "绝缘采样使能位_IMM26";
CM_ SG_ 2332113565 M2I_Byrack_ReVeEnable_IMM26_13 "读取软件版本使能位_IMM26";
CM_ SG_ 2332113565 Reserved_13 "预留预留";
CM_ SG_ 2332113565 M2I_Byrack_IsPostTm_IMM26_13 "绝缘采样时间_IMM26";
CM_ SG_ 2332113565 M2I_Byrack_SysABStTm_IMM26_13 "电压稳定时间_IMM26";
CM_ SG_ 2332113566 CRC_M2I_Byrack_IMM26_14 "CRC校验_IMM26";
CM_ SG_ 2332113566 M2I_Byrack_HVS_IMM26_14 "绝缘测量电压_IMM26";
CM_ SG_ 2332113566 M2I_Byrack_Enable_IMM26_14 "绝缘采样使能位_IMM26";
CM_ SG_ 2332113566 M2I_Byrack_ReVeEnable_IMM26_14 "读取软件版本使能位_IMM26";
CM_ SG_ 2332113566 Reserved_14 "预留预留";
CM_ SG_ 2332113566 M2I_Byrack_IsPostTm_IMM26_14 "绝缘采样时间_IMM26";
CM_ SG_ 2332113566 M2I_Byrack_SysABStTm_IMM26_14 "电压稳定时间_IMM26";
CM_ SG_ 2332113567 CRC_M2I_Byrack_IMM26_15 "CRC校验_IMM26";
CM_ SG_ 2332113567 M2I_Byrack_HVS_IMM26_15 "绝缘测量电压_IMM26";
CM_ SG_ 2332113567 M2I_Byrack_Enable_IMM26_15 "绝缘采样使能位_IMM26";
CM_ SG_ 2332113567 M2I_Byrack_ReVeEnable_IMM26_15 "读取软件版本使能位_IMM26";
CM_ SG_ 2332113567 Reserved_15 "预留预留";
CM_ SG_ 2332113567 M2I_Byrack_IsPostTm_IMM26_15 "绝缘采样时间_IMM26";
CM_ SG_ 2332113567 M2I_Byrack_SysABStTm_IMM26_15 "电压稳定时间_IMM26";
CM_ SG_ 2332113568 CRC_M2I_Byrack_IMM26_16 "CRC校验_IMM26";
CM_ SG_ 2332113568 M2I_Byrack_HVS_IMM26_16 "绝缘测量电压_IMM26";
CM_ SG_ 2332113568 M2I_Byrack_Enable_IMM26_16 "绝缘采样使能位_IMM26";
CM_ SG_ 2332113568 M2I_Byrack_ReVeEnable_IMM26_16 "读取软件版本使能位_IMM26";
CM_ SG_ 2332113568 Reserved_16 "预留预留";
CM_ SG_ 2332113568 M2I_Byrack_IsPostTm_IMM26_16 "绝缘采样时间_IMM26";
CM_ SG_ 2332113568 M2I_Byrack_SysABStTm_IMM26_16 "电压稳定时间_IMM26";
CM_ SG_ 2332113569 CRC_M2I_Byrack_IMM26_17 "CRC校验_IMM26";
CM_ SG_ 2332113569 M2I_Byrack_HVS_IMM26_17 "绝缘测量电压_IMM26";
CM_ SG_ 2332113569 M2I_Byrack_Enable_IMM26_17 "绝缘采样使能位_IMM26";
CM_ SG_ 2332113569 M2I_Byrack_ReVeEnable_IMM26_17 "读取软件版本使能位_IMM26";
CM_ SG_ 2332113569 Reserved_17 "预留预留";
CM_ SG_ 2332113569 M2I_Byrack_IsPostTm_IMM26_17 "绝缘采样时间_IMM26";
CM_ SG_ 2332113569 M2I_Byrack_SysABStTm_IMM26_17 "电压稳定时间_IMM26";
CM_ SG_ 2332113570 CRC_M2I_Byrack_IMM26_18 "CRC校验_IMM26";
CM_ SG_ 2332113570 M2I_Byrack_HVS_IMM26_18 "绝缘测量电压_IMM26";
CM_ SG_ 2332113570 M2I_Byrack_Enable_IMM26_18 "绝缘采样使能位_IMM26";
CM_ SG_ 2332113570 M2I_Byrack_ReVeEnable_IMM26_18 "读取软件版本使能位_IMM26";
CM_ SG_ 2332113570 Reserved_18 "预留预留";
CM_ SG_ 2332113570 M2I_Byrack_IsPostTm_IMM26_18 "绝缘采样时间_IMM26";
CM_ SG_ 2332113570 M2I_Byrack_SysABStTm_IMM26_18 "电压稳定时间_IMM26";
CM_ SG_ 2332113571 CRC_M2I_Byrack_IMM26_19 "CRC校验_IMM26";
CM_ SG_ 2332113571 M2I_Byrack_HVS_IMM26_19 "绝缘测量电压_IMM26";
CM_ SG_ 2332113571 M2I_Byrack_Enable_IMM26_19 "绝缘采样使能位_IMM26";
CM_ SG_ 2332113571 M2I_Byrack_ReVeEnable_IMM26_19 "读取软件版本使能位_IMM26";
CM_ SG_ 2332113571 Reserved_19 "预留预留";
CM_ SG_ 2332113571 M2I_Byrack_IsPostTm_IMM26_19 "绝缘采样时间_IMM26";
CM_ SG_ 2332113571 M2I_Byrack_SysABStTm_IMM26_19 "电压稳定时间_IMM26";
CM_ SG_ 2332113572 CRC_M2I_Byrack_IMM26_20 "CRC校验_IMM26";
CM_ SG_ 2332113572 M2I_Byrack_HVS_IMM26_20 "绝缘测量电压_IMM26";
CM_ SG_ 2332113572 M2I_Byrack_Enable_IMM26_20 "绝缘采样使能位_IMM26";
CM_ SG_ 2332113572 M2I_Byrack_ReVeEnable_IMM26_20 "读取软件版本使能位_IMM26";
CM_ SG_ 2332113572 Reserved_20 "预留预留";
CM_ SG_ 2332113572 M2I_Byrack_IsPostTm_IMM26_20 "绝缘采样时间_IMM26";
CM_ SG_ 2332113572 M2I_Byrack_SysABStTm_IMM26_20 "电压稳定时间_IMM26";
CM_ SG_ 2332113573 CRC_M2I_Byrack_IMM26_21 "CRC校验_IMM26";
CM_ SG_ 2332113573 M2I_Byrack_HVS_IMM26_21 "绝缘测量电压_IMM26";
CM_ SG_ 2332113573 M2I_Byrack_Enable_IMM26_21 "绝缘采样使能位_IMM26";
CM_ SG_ 2332113573 M2I_Byrack_ReVeEnable_IMM26_21 "读取软件版本使能位_IMM26";
CM_ SG_ 2332113573 Reserved_21 "预留预留";
CM_ SG_ 2332113573 M2I_Byrack_IsPostTm_IMM26_21 "绝缘采样时间_IMM26";
CM_ SG_ 2332113573 M2I_Byrack_SysABStTm_IMM26_21 "电压稳定时间_IMM26";
CM_ SG_ 2332113574 CRC_M2I_Byrack_IMM26_22 "CRC校验_IMM26";
CM_ SG_ 2332113574 M2I_Byrack_HVS_IMM26_22 "绝缘测量电压_IMM26";
CM_ SG_ 2332113574 M2I_Byrack_Enable_IMM26_22 "绝缘采样使能位_IMM26";
CM_ SG_ 2332113574 M2I_Byrack_ReVeEnable_IMM26_22 "读取软件版本使能位_IMM26";
CM_ SG_ 2332113574 Reserved_22 "预留预留";
CM_ SG_ 2332113574 M2I_Byrack_IsPostTm_IMM26_22 "绝缘采样时间_IMM26";
CM_ SG_ 2332113574 M2I_Byrack_SysABStTm_IMM26_22 "电压稳定时间_IMM26";
CM_ SG_ 2332113575 CRC_M2I_Byrack_IMM26_23 "CRC校验_IMM26";
CM_ SG_ 2332113575 M2I_Byrack_HVS_IMM26_23 "绝缘测量电压_IMM26";
CM_ SG_ 2332113575 M2I_Byrack_Enable_IMM26_23 "绝缘采样使能位_IMM26";
CM_ SG_ 2332113575 M2I_Byrack_ReVeEnable_IMM26_23 "读取软件版本使能位_IMM26";
CM_ SG_ 2332113575 Reserved_23 "预留预留";
CM_ SG_ 2332113575 M2I_Byrack_IsPostTm_IMM26_23 "绝缘采样时间_IMM26";
CM_ SG_ 2332113575 M2I_Byrack_SysABStTm_IMM26_23 "电压稳定时间_IMM26";
CM_ SG_ 2332113576 CRC_M2I_Byrack_IMM26_24 "CRC校验_IMM26";
CM_ SG_ 2332113576 M2I_Byrack_HVS_IMM26_24 "绝缘测量电压_IMM26";
CM_ SG_ 2332113576 M2I_Byrack_Enable_IMM26_24 "绝缘采样使能位_IMM26";
CM_ SG_ 2332113576 M2I_Byrack_ReVeEnable_IMM26_24 "读取软件版本使能位_IMM26";
CM_ SG_ 2332113576 Reserved_24 "预留预留";
CM_ SG_ 2332113576 M2I_Byrack_IsPostTm_IMM26_24 "绝缘采样时间_IMM26";
CM_ SG_ 2332113576 M2I_Byrack_SysABStTm_IMM26_24 "电压稳定时间_IMM26";
CM_ SG_ 2332113577 CRC_M2I_Byrack_IMM26_25 "CRC校验_IMM26";
CM_ SG_ 2332113577 M2I_Byrack_HVS_IMM26_25 "绝缘测量电压_IMM26";
CM_ SG_ 2332113577 M2I_Byrack_Enable_IMM26_25 "绝缘采样使能位_IMM26";
CM_ SG_ 2332113577 M2I_Byrack_ReVeEnable_IMM26_25 "读取软件版本使能位_IMM26";
CM_ SG_ 2332113577 Reserved_25 "预留预留";
CM_ SG_ 2332113577 M2I_Byrack_IsPostTm_IMM26_25 "绝缘采样时间_IMM26";
CM_ SG_ 2332113577 M2I_Byrack_SysABStTm_IMM26_25 "电压稳定时间_IMM26";
CM_ SG_ 2332113578 CRC_M2I_Byrack_IMM26_26 "CRC校验_IMM26";
CM_ SG_ 2332113578 M2I_Byrack_HVS_IMM26_26 "绝缘测量电压_IMM26";
CM_ SG_ 2332113578 M2I_Byrack_Enable_IMM26_26 "绝缘采样使能位_IMM26";
CM_ SG_ 2332113578 M2I_Byrack_ReVeEnable_IMM26_26 "读取软件版本使能位_IMM26";
CM_ SG_ 2332113578 Reserved_26 "预留预留";
CM_ SG_ 2332113578 M2I_Byrack_IsPostTm_IMM26_26 "绝缘采样时间_IMM26";
CM_ SG_ 2332113578 M2I_Byrack_SysABStTm_IMM26_26 "电压稳定时间_IMM26";
VAL_ 2332112289 M2I_Byrack_Enable_IMM21_17 1 "Deactive" 2 "Active" ;
VAL_ 2332112289 M2I_Byrack_ReVeEnable_IMM21_17 0 "invalid" 1 "Read SW-Version" 2 "Read HW-Version" 3 "Barcode" ;
VAL_ 2332112290 M2I_Byrack_Enable_IMM21_18 1 "Deactive" 2 "Active" ;
VAL_ 2332112290 M2I_Byrack_ReVeEnable_IMM21_18 0 "invalid" 1 "Read SW-Version" 2 "Read HW-Version" 3 "Barcode" ;
VAL_ 2332112291 M2I_Byrack_Enable_IMM21_19 1 "Deactive" 2 "Active" ;
VAL_ 2332112291 M2I_Byrack_ReVeEnable_IMM21_19 0 "invalid" 1 "Read SW-Version" 2 "Read HW-Version" 3 "Barcode" ;
VAL_ 2332112292 M2I_Byrack_Enable_IMM21_20 1 "Deactive" 2 "Active" ;
VAL_ 2332112292 M2I_Byrack_ReVeEnable_IMM21_20 0 "invalid" 1 "Read SW-Version" 2 "Read HW-Version" 3 "Barcode" ;
VAL_ 2332112293 M2I_Byrack_Enable_IMM21_21 1 "Deactive" 2 "Active" ;
VAL_ 2332112293 M2I_Byrack_ReVeEnable_IMM21_21 0 "invalid" 1 "Read SW-Version" 2 "Read HW-Version" 3 "Barcode" ;
VAL_ 2332112294 M2I_Byrack_Enable_IMM21_22 1 "Deactive" 2 "Active" ;
VAL_ 2332112294 M2I_Byrack_ReVeEnable_IMM21_22 0 "invalid" 1 "Read SW-Version" 2 "Read HW-Version" 3 "Barcode" ;
VAL_ 2332112295 M2I_Byrack_Enable_IMM21_23 1 "Deactive" 2 "Active" ;
VAL_ 2332112295 M2I_Byrack_ReVeEnable_IMM21_23 0 "invalid" 1 "Read SW-Version" 2 "Read HW-Version" 3 "Barcode" ;
VAL_ 2332112296 M2I_Byrack_Enable_IMM21_24 1 "Deactive" 2 "Active" ;
VAL_ 2332112296 M2I_Byrack_ReVeEnable_IMM21_24 0 "invalid" 1 "Read SW-Version" 2 "Read HW-Version" 3 "Barcode" ;
VAL_ 2332112297 M2I_Byrack_Enable_IMM21_25 1 "Deactive" 2 "Active" ;
VAL_ 2332112297 M2I_Byrack_ReVeEnable_IMM21_25 0 "invalid" 1 "Read SW-Version" 2 "Read HW-Version" 3 "Barcode" ;
VAL_ 2332112298 M2I_Byrack_Enable_IMM21_26 1 "Deactive" 2 "Active" ;
VAL_ 2332112298 M2I_Byrack_ReVeEnable_IMM21_26 0 "invalid" 1 "Read SW-Version" 2 "Read HW-Version" 3 "Barcode" ;
VAL_ 2332112299 M2I_Byrack_Enable_IMM21_27 1 "Deactive" 2 "Active" ;
VAL_ 2332112299 M2I_Byrack_ReVeEnable_IMM21_27 0 "invalid" 1 "Read SW-Version" 2 "Read HW-Version" 3 "Barcode" ;
VAL_ 2332112300 M2I_Byrack_Enable_IMM21_28 1 "Deactive" 2 "Active" ;
VAL_ 2332112300 M2I_Byrack_ReVeEnable_IMM21_28 0 "invalid" 1 "Read SW-Version" 2 "Read HW-Version" 3 "Barcode" ;
VAL_ 2332112301 M2I_Byrack_Enable_IMM21_29 1 "Deactive" 2 "Active" ;
VAL_ 2332112301 M2I_Byrack_ReVeEnable_IMM21_29 0 "invalid" 1 "Read SW-Version" 2 "Read HW-Version" 3 "Barcode" ;
VAL_ 2332112302 M2I_Byrack_Enable_IMM21_30 1 "Deactive" 2 "Active" ;
VAL_ 2332112302 M2I_Byrack_ReVeEnable_IMM21_30 0 "invalid" 1 "Read SW-Version" 2 "Read HW-Version" 3 "Barcode" ;
VAL_ 2332112303 M2I_Byrack_Enable_IMM21_31 1 "Deactive" 2 "Active" ;
VAL_ 2332112303 M2I_Byrack_ReVeEnable_IMM21_31 0 "invalid" 1 "Read SW-Version" 2 "Read HW-Version" 3 "Barcode" ;
VAL_ 2332112529 M2I_Byrack_Enable_IMM22_01 1 "Deactive" 2 "Active" ;
VAL_ 2332112529 M2I_Byrack_ReVeEnable_IMM22_01 0 "invalid" 1 "Read SW-Version" 2 "Read HW-Version" 3 "Barcode" ;
VAL_ 2332112530 M2I_Byrack_Enable_IMM22_02 1 "Deactive" 2 "Active" ;
VAL_ 2332112530 M2I_Byrack_ReVeEnable_IMM22_02 0 "invalid" 1 "Read SW-Version" 2 "Read HW-Version" 3 "Barcode" ;
VAL_ 2332112531 M2I_Byrack_Enable_IMM22_03 1 "Deactive" 2 "Active" ;
VAL_ 2332112531 M2I_Byrack_ReVeEnable_IMM22_03 0 "invalid" 1 "Read SW-Version" 2 "Read HW-Version" 3 "Barcode" ;
VAL_ 2332112532 M2I_Byrack_Enable_IMM22_04 1 "Deactive" 2 "Active" ;
VAL_ 2332112532 M2I_Byrack_ReVeEnable_IMM22_04 0 "invalid" 1 "Read SW-Version" 2 "Read HW-Version" 3 "Barcode" ;
VAL_ 2332112533 M2I_Byrack_Enable_IMM22_05 1 "Deactive" 2 "Active" ;
VAL_ 2332112533 M2I_Byrack_ReVeEnable_IMM22_05 0 "invalid" 1 "Read SW-Version" 2 "Read HW-Version" 3 "Barcode" ;
VAL_ 2332112534 M2I_Byrack_Enable_IMM22_06 1 "Deactive" 2 "Active" ;
VAL_ 2332112534 M2I_Byrack_ReVeEnable_IMM22_06 0 "invalid" 1 "Read SW-Version" 2 "Read HW-Version" 3 "Barcode" ;
VAL_ 2332112535 M2I_Byrack_Enable_IMM22_07 1 "Deactive" 2 "Active" ;
VAL_ 2332112535 M2I_Byrack_ReVeEnable_IMM22_07 0 "invalid" 1 "Read SW-Version" 2 "Read HW-Version" 3 "Barcode" ;
VAL_ 2332112536 M2I_Byrack_Enable_IMM22_08 1 "Deactive" 2 "Active" ;
VAL_ 2332112536 M2I_Byrack_ReVeEnable_IMM22_08 0 "invalid" 1 "Read SW-Version" 2 "Read HW-Version" 3 "Barcode" ;
VAL_ 2332112537 M2I_Byrack_Enable_IMM22_09 1 "Deactive" 2 "Active" ;
VAL_ 2332112537 M2I_Byrack_ReVeEnable_IMM22_09 0 "invalid" 1 "Read SW-Version" 2 "Read HW-Version" 3 "Barcode" ;
VAL_ 2332112538 M2I_Byrack_Enable_IMM22_10 1 "Deactive" 2 "Active" ;
VAL_ 2332112538 M2I_Byrack_ReVeEnable_IMM22_10 0 "invalid" 1 "Read SW-Version" 2 "Read HW-Version" 3 "Barcode" ;
VAL_ 2332112539 M2I_Byrack_Enable_IMM22_11 1 "Deactive" 2 "Active" ;
VAL_ 2332112539 M2I_Byrack_ReVeEnable_IMM22_11 0 "invalid" 1 "Read SW-Version" 2 "Read HW-Version" 3 "Barcode" ;
VAL_ 2332112540 M2I_Byrack_Enable_IMM22_12 1 "Deactive" 2 "Active" ;
VAL_ 2332112540 M2I_Byrack_ReVeEnable_IMM22_12 0 "invalid" 1 "Read SW-Version" 2 "Read HW-Version" 3 "Barcode" ;
VAL_ 2332112541 M2I_Byrack_Enable_IMM22_13 1 "Deactive" 2 "Active" ;
VAL_ 2332112541 M2I_Byrack_ReVeEnable_IMM22_13 0 "invalid" 1 "Read SW-Version" 2 "Read HW-Version" 3 "Barcode" ;
VAL_ 2332112542 M2I_Byrack_Enable_IMM22_14 1 "Deactive" 2 "Active" ;
VAL_ 2332112542 M2I_Byrack_ReVeEnable_IMM22_14 0 "invalid" 1 "Read SW-Version" 2 "Read HW-Version" 3 "Barcode" ;
VAL_ 2332112543 M2I_Byrack_Enable_IMM22_15 1 "Deactive" 2 "Active" ;
VAL_ 2332112543 M2I_Byrack_ReVeEnable_IMM22_15 0 "invalid" 1 "Read SW-Version" 2 "Read HW-Version" 3 "Barcode" ;
VAL_ 2332112544 M2I_Byrack_Enable_IMM22_16 1 "Deactive" 2 "Active" ;
VAL_ 2332112544 M2I_Byrack_ReVeEnable_IMM22_16 0 "invalid" 1 "Read SW-Version" 2 "Read HW-Version" 3 "Barcode" ;
VAL_ 2332112545 M2I_Byrack_Enable_IMM22_17 1 "Deactive" 2 "Active" ;
VAL_ 2332112545 M2I_Byrack_ReVeEnable_IMM22_17 0 "invalid" 1 "Read SW-Version" 2 "Read HW-Version" 3 "Barcode" ;
VAL_ 2332112546 M2I_Byrack_Enable_IMM22_18 1 "Deactive" 2 "Active" ;
VAL_ 2332112546 M2I_Byrack_ReVeEnable_IMM22_18 0 "invalid" 1 "Read SW-Version" 2 "Read HW-Version" 3 "Barcode" ;
VAL_ 2332112547 M2I_Byrack_Enable_IMM22_19 1 "Deactive" 2 "Active" ;
VAL_ 2332112547 M2I_Byrack_ReVeEnable_IMM22_19 0 "invalid" 1 "Read SW-Version" 2 "Read HW-Version" 3 "Barcode" ;
VAL_ 2332112548 M2I_Byrack_Enable_IMM22_20 1 "Deactive" 2 "Active" ;
VAL_ 2332112548 M2I_Byrack_ReVeEnable_IMM22_20 0 "invalid" 1 "Read SW-Version" 2 "Read HW-Version" 3 "Barcode" ;
VAL_ 2332112549 M2I_Byrack_Enable_IMM22_21 1 "Deactive" 2 "Active" ;
VAL_ 2332112549 M2I_Byrack_ReVeEnable_IMM22_21 0 "invalid" 1 "Read SW-Version" 2 "Read HW-Version" 3 "Barcode" ;
VAL_ 2332112550 M2I_Byrack_Enable_IMM22_22 1 "Deactive" 2 "Active" ;
VAL_ 2332112550 M2I_Byrack_ReVeEnable_IMM22_22 0 "invalid" 1 "Read SW-Version" 2 "Read HW-Version" 3 "Barcode" ;
VAL_ 2332112551 M2I_Byrack_Enable_IMM22_23 1 "Deactive" 2 "Active" ;
VAL_ 2332112551 M2I_Byrack_ReVeEnable_IMM22_23 0 "invalid" 1 "Read SW-Version" 2 "Read HW-Version" 3 "Barcode" ;
VAL_ 2332112552 M2I_Byrack_Enable_IMM22_24 1 "Deactive" 2 "Active" ;
VAL_ 2332112552 M2I_Byrack_ReVeEnable_IMM22_24 0 "invalid" 1 "Read SW-Version" 2 "Read HW-Version" 3 "Barcode" ;
VAL_ 2332112553 M2I_Byrack_Enable_IMM22_25 1 "Deactive" 2 "Active" ;
VAL_ 2332112553 M2I_Byrack_ReVeEnable_IMM22_25 0 "invalid" 1 "Read SW-Version" 2 "Read HW-Version" 3 "Barcode" ;
VAL_ 2332112554 M2I_Byrack_Enable_IMM22_26 1 "Deactive" 2 "Active" ;
VAL_ 2332112554 M2I_Byrack_ReVeEnable_IMM22_26 0 "invalid" 1 "Read SW-Version" 2 "Read HW-Version" 3 "Barcode" ;
VAL_ 2332112555 M2I_Byrack_Enable_IMM22_27 1 "Deactive" 2 "Active" ;
VAL_ 2332112555 M2I_Byrack_ReVeEnable_IMM22_27 0 "invalid" 1 "Read SW-Version" 2 "Read HW-Version" 3 "Barcode" ;
VAL_ 2332112556 M2I_Byrack_Enable_IMM22_28 1 "Deactive" 2 "Active" ;
VAL_ 2332112556 M2I_Byrack_ReVeEnable_IMM22_28 0 "invalid" 1 "Read SW-Version" 2 "Read HW-Version" 3 "Barcode" ;
VAL_ 2332112557 M2I_Byrack_Enable_IMM22_29 1 "Deactive" 2 "Active" ;
VAL_ 2332112557 M2I_Byrack_ReVeEnable_IMM22_29 0 "invalid" 1 "Read SW-Version" 2 "Read HW-Version" 3 "Barcode" ;
VAL_ 2332112558 M2I_Byrack_Enable_IMM22_30 1 "Deactive" 2 "Active" ;
VAL_ 2332112558 M2I_Byrack_ReVeEnable_IMM22_30 0 "invalid" 1 "Read SW-Version" 2 "Read HW-Version" 3 "Barcode" ;
VAL_ 2332112559 M2I_Byrack_Enable_IMM22_31 1 "Deactive" 2 "Active" ;
VAL_ 2332112559 M2I_Byrack_ReVeEnable_IMM22_31 0 "invalid" 1 "Read SW-Version" 2 "Read HW-Version" 3 "Barcode" ;
VAL_ 2332112785 M2I_Byrack_Enable_IMM23_01 1 "Deactive" 2 "Active" ;
VAL_ 2332112785 M2I_Byrack_ReVeEnable_IMM23_01 0 "invalid" 1 "Read SW-Version" 2 "Read HW-Version" 3 "Barcode" ;
VAL_ 2332112786 M2I_Byrack_Enable_IMM23_02 1 "Deactive" 2 "Active" ;
VAL_ 2332112786 M2I_Byrack_ReVeEnable_IMM23_02 0 "invalid" 1 "Read SW-Version" 2 "Read HW-Version" 3 "Barcode" ;
VAL_ 2332112787 M2I_Byrack_Enable_IMM23_03 1 "Deactive" 2 "Active" ;
VAL_ 2332112787 M2I_Byrack_ReVeEnable_IMM23_03 0 "invalid" 1 "Read SW-Version" 2 "Read HW-Version" 3 "Barcode" ;
VAL_ 2332112788 M2I_Byrack_Enable_IMM23_04 1 "Deactive" 2 "Active" ;
VAL_ 2332112788 M2I_Byrack_ReVeEnable_IMM23_04 0 "invalid" 1 "Read SW-Version" 2 "Read HW-Version" 3 "Barcode" ;
VAL_ 2332112789 M2I_Byrack_Enable_IMM23_05 1 "Deactive" 2 "Active" ;
VAL_ 2332112789 M2I_Byrack_ReVeEnable_IMM23_05 0 "invalid" 1 "Read SW-Version" 2 "Read HW-Version" 3 "Barcode" ;
VAL_ 2332112790 M2I_Byrack_Enable_IMM23_06 1 "Deactive" 2 "Active" ;
VAL_ 2332112790 M2I_Byrack_ReVeEnable_IMM23_06 0 "invalid" 1 "Read SW-Version" 2 "Read HW-Version" 3 "Barcode" ;
VAL_ 2332112791 M2I_Byrack_Enable_IMM23_07 1 "Deactive" 2 "Active" ;
VAL_ 2332112791 M2I_Byrack_ReVeEnable_IMM23_07 0 "invalid" 1 "Read SW-Version" 2 "Read HW-Version" 3 "Barcode" ;
VAL_ 2332112792 M2I_Byrack_Enable_IMM23_08 1 "Deactive" 2 "Active" ;
VAL_ 2332112792 M2I_Byrack_ReVeEnable_IMM23_08 0 "invalid" 1 "Read SW-Version" 2 "Read HW-Version" 3 "Barcode" ;
VAL_ 2332112793 M2I_Byrack_Enable_IMM23_09 1 "Deactive" 2 "Active" ;
VAL_ 2332112793 M2I_Byrack_ReVeEnable_IMM23_09 0 "invalid" 1 "Read SW-Version" 2 "Read HW-Version" 3 "Barcode" ;
VAL_ 2332112794 M2I_Byrack_Enable_IMM23_10 1 "Deactive" 2 "Active" ;
VAL_ 2332112794 M2I_Byrack_ReVeEnable_IMM23_10 0 "invalid" 1 "Read SW-Version" 2 "Read HW-Version" 3 "Barcode" ;
VAL_ 2332112795 M2I_Byrack_Enable_IMM23_11 1 "Deactive" 2 "Active" ;
VAL_ 2332112795 M2I_Byrack_ReVeEnable_IMM23_11 0 "invalid" 1 "Read SW-Version" 2 "Read HW-Version" 3 "Barcode" ;
VAL_ 2332112796 M2I_Byrack_Enable_IMM23_12 1 "Deactive" 2 "Active" ;
VAL_ 2332112796 M2I_Byrack_ReVeEnable_IMM23_12 0 "invalid" 1 "Read SW-Version" 2 "Read HW-Version" 3 "Barcode" ;
VAL_ 2332112797 M2I_Byrack_Enable_IMM23_13 1 "Deactive" 2 "Active" ;
VAL_ 2332112797 M2I_Byrack_ReVeEnable_IMM23_13 0 "invalid" 1 "Read SW-Version" 2 "Read HW-Version" 3 "Barcode" ;
VAL_ 2332112798 M2I_Byrack_Enable_IMM23_14 1 "Deactive" 2 "Active" ;
VAL_ 2332112798 M2I_Byrack_ReVeEnable_IMM23_14 0 "invalid" 1 "Read SW-Version" 2 "Read HW-Version" 3 "Barcode" ;
VAL_ 2332112799 M2I_Byrack_Enable_IMM23_15 1 "Deactive" 2 "Active" ;
VAL_ 2332112799 M2I_Byrack_ReVeEnable_IMM23_15 0 "invalid" 1 "Read SW-Version" 2 "Read HW-Version" 3 "Barcode" ;
VAL_ 2332112800 M2I_Byrack_Enable_IMM23_16 1 "Deactive" 2 "Active" ;
VAL_ 2332112800 M2I_Byrack_ReVeEnable_IMM23_16 0 "invalid" 1 "Read SW-Version" 2 "Read HW-Version" 3 "Barcode" ;
VAL_ 2332112801 M2I_Byrack_Enable_IMM23_17 1 "Deactive" 2 "Active" ;
VAL_ 2332112801 M2I_Byrack_ReVeEnable_IMM23_17 0 "invalid" 1 "Read SW-Version" 2 "Read HW-Version" 3 "Barcode" ;
VAL_ 2332112802 M2I_Byrack_Enable_IMM23_18 1 "Deactive" 2 "Active" ;
VAL_ 2332112802 M2I_Byrack_ReVeEnable_IMM23_18 0 "invalid" 1 "Read SW-Version" 2 "Read HW-Version" 3 "Barcode" ;
VAL_ 2332112803 M2I_Byrack_Enable_IMM23_19 1 "Deactive" 2 "Active" ;
VAL_ 2332112803 M2I_Byrack_ReVeEnable_IMM23_19 0 "invalid" 1 "Read SW-Version" 2 "Read HW-Version" 3 "Barcode" ;
VAL_ 2332112804 M2I_Byrack_Enable_IMM23_20 1 "Deactive" 2 "Active" ;
VAL_ 2332112804 M2I_Byrack_ReVeEnable_IMM23_20 0 "invalid" 1 "Read SW-Version" 2 "Read HW-Version" 3 "Barcode" ;
VAL_ 2332112805 M2I_Byrack_Enable_IMM23_21 1 "Deactive" 2 "Active" ;
VAL_ 2332112805 M2I_Byrack_ReVeEnable_IMM23_21 0 "invalid" 1 "Read SW-Version" 2 "Read HW-Version" 3 "Barcode" ;
VAL_ 2332112806 M2I_Byrack_Enable_IMM23_22 1 "Deactive" 2 "Active" ;
VAL_ 2332112806 M2I_Byrack_ReVeEnable_IMM23_22 0 "invalid" 1 "Read SW-Version" 2 "Read HW-Version" 3 "Barcode" ;
VAL_ 2332112807 M2I_Byrack_Enable_IMM23_23 1 "Deactive" 2 "Active" ;
VAL_ 2332112807 M2I_Byrack_ReVeEnable_IMM23_23 0 "invalid" 1 "Read SW-Version" 2 "Read HW-Version" 3 "Barcode" ;
VAL_ 2332112808 M2I_Byrack_Enable_IMM23_24 1 "Deactive" 2 "Active" ;
VAL_ 2332112808 M2I_Byrack_ReVeEnable_IMM23_24 0 "invalid" 1 "Read SW-Version" 2 "Read HW-Version" 3 "Barcode" ;
VAL_ 2332112809 M2I_Byrack_Enable_IMM23_25 1 "Deactive" 2 "Active" ;
VAL_ 2332112809 M2I_Byrack_ReVeEnable_IMM23_25 0 "invalid" 1 "Read SW-Version" 2 "Read HW-Version" 3 "Barcode" ;
VAL_ 2332112810 M2I_Byrack_Enable_IMM23_26 1 "Deactive" 2 "Active" ;
VAL_ 2332112810 M2I_Byrack_ReVeEnable_IMM23_26 0 "invalid" 1 "Read SW-Version" 2 "Read HW-Version" 3 "Barcode" ;
VAL_ 2332112811 M2I_Byrack_Enable_IMM23_27 1 "Deactive" 2 "Active" ;
VAL_ 2332112811 M2I_Byrack_ReVeEnable_IMM23_27 0 "invalid" 1 "Read SW-Version" 2 "Read HW-Version" 3 "Barcode" ;
VAL_ 2332112812 M2I_Byrack_Enable_IMM23_28 1 "Deactive" 2 "Active" ;
VAL_ 2332112812 M2I_Byrack_ReVeEnable_IMM23_28 0 "invalid" 1 "Read SW-Version" 2 "Read HW-Version" 3 "Barcode" ;
VAL_ 2332112813 M2I_Byrack_Enable_IMM23_29 1 "Deactive" 2 "Active" ;
VAL_ 2332112813 M2I_Byrack_ReVeEnable_IMM23_29 0 "invalid" 1 "Read SW-Version" 2 "Read HW-Version" 3 "Barcode" ;
VAL_ 2332112814 M2I_Byrack_Enable_IMM23_30 1 "Deactive" 2 "Active" ;
VAL_ 2332112814 M2I_Byrack_ReVeEnable_IMM23_30 0 "invalid" 1 "Read SW-Version" 2 "Read HW-Version" 3 "Barcode" ;
VAL_ 2332112815 M2I_Byrack_Enable_IMM23_31 1 "Deactive" 2 "Active" ;
VAL_ 2332112815 M2I_Byrack_ReVeEnable_IMM23_31 0 "invalid" 1 "Read SW-Version" 2 "Read HW-Version" 3 "Barcode" ;
VAL_ 2332113041 M2I_Byrack_Enable_IMM24_01 1 "Deactive" 2 "Active" ;
VAL_ 2332113041 M2I_Byrack_ReVeEnable_IMM24_01 0 "invalid" 1 "Read SW-Version" 2 "Read HW-Version" 3 "Barcode" ;
VAL_ 2332113042 M2I_Byrack_Enable_IMM24_02 1 "Deactive" 2 "Active" ;
VAL_ 2332113042 M2I_Byrack_ReVeEnable_IMM24_02 0 "invalid" 1 "Read SW-Version" 2 "Read HW-Version" 3 "Barcode" ;
VAL_ 2332113043 M2I_Byrack_Enable_IMM24_03 1 "Deactive" 2 "Active" ;
VAL_ 2332113043 M2I_Byrack_ReVeEnable_IMM24_03 0 "invalid" 1 "Read SW-Version" 2 "Read HW-Version" 3 "Barcode" ;
VAL_ 2332113044 M2I_Byrack_Enable_IMM24_04 1 "Deactive" 2 "Active" ;
VAL_ 2332113044 M2I_Byrack_ReVeEnable_IMM24_04 0 "invalid" 1 "Read SW-Version" 2 "Read HW-Version" 3 "Barcode" ;
VAL_ 2332113045 M2I_Byrack_Enable_IMM24_05 1 "Deactive" 2 "Active" ;
VAL_ 2332113045 M2I_Byrack_ReVeEnable_IMM24_05 0 "invalid" 1 "Read SW-Version" 2 "Read HW-Version" 3 "Barcode" ;
VAL_ 2332113046 M2I_Byrack_Enable_IMM24_06 1 "Deactive" 2 "Active" ;
VAL_ 2332113046 M2I_Byrack_ReVeEnable_IMM24_06 0 "invalid" 1 "Read SW-Version" 2 "Read HW-Version" 3 "Barcode" ;
VAL_ 2332113047 M2I_Byrack_Enable_IMM24_07 1 "Deactive" 2 "Active" ;
VAL_ 2332113047 M2I_Byrack_ReVeEnable_IMM24_07 0 "invalid" 1 "Read SW-Version" 2 "Read HW-Version" 3 "Barcode" ;
VAL_ 2332113048 M2I_Byrack_Enable_IMM24_08 1 "Deactive" 2 "Active" ;
VAL_ 2332113048 M2I_Byrack_ReVeEnable_IMM24_08 0 "invalid" 1 "Read SW-Version" 2 "Read HW-Version" 3 "Barcode" ;
VAL_ 2332113049 M2I_Byrack_Enable_IMM24_09 1 "Deactive" 2 "Active" ;
VAL_ 2332113049 M2I_Byrack_ReVeEnable_IMM24_09 0 "invalid" 1 "Read SW-Version" 2 "Read HW-Version" 3 "Barcode" ;
VAL_ 2332113050 M2I_Byrack_Enable_IMM24_10 1 "Deactive" 2 "Active" ;
VAL_ 2332113050 M2I_Byrack_ReVeEnable_IMM24_10 0 "invalid" 1 "Read SW-Version" 2 "Read HW-Version" 3 "Barcode" ;
VAL_ 2332113051 M2I_Byrack_Enable_IMM24_11 1 "Deactive" 2 "Active" ;
VAL_ 2332113051 M2I_Byrack_ReVeEnable_IMM24_11 0 "invalid" 1 "Read SW-Version" 2 "Read HW-Version" 3 "Barcode" ;
VAL_ 2332113052 M2I_Byrack_Enable_IMM24_12 1 "Deactive" 2 "Active" ;
VAL_ 2332113052 M2I_Byrack_ReVeEnable_IMM24_12 0 "invalid" 1 "Read SW-Version" 2 "Read HW-Version" 3 "Barcode" ;
VAL_ 2332113053 M2I_Byrack_Enable_IMM24_13 1 "Deactive" 2 "Active" ;
VAL_ 2332113053 M2I_Byrack_ReVeEnable_IMM24_13 0 "invalid" 1 "Read SW-Version" 2 "Read HW-Version" 3 "Barcode" ;
VAL_ 2332113054 M2I_Byrack_Enable_IMM24_14 1 "Deactive" 2 "Active" ;
VAL_ 2332113054 M2I_Byrack_ReVeEnable_IMM24_14 0 "invalid" 1 "Read SW-Version" 2 "Read HW-Version" 3 "Barcode" ;
VAL_ 2332113055 M2I_Byrack_Enable_IMM24_15 1 "Deactive" 2 "Active" ;
VAL_ 2332113055 M2I_Byrack_ReVeEnable_IMM24_15 0 "invalid" 1 "Read SW-Version" 2 "Read HW-Version" 3 "Barcode" ;
VAL_ 2332113056 M2I_Byrack_Enable_IMM24_16 1 "Deactive" 2 "Active" ;
VAL_ 2332113056 M2I_Byrack_ReVeEnable_IMM24_16 0 "invalid" 1 "Read SW-Version" 2 "Read HW-Version" 3 "Barcode" ;
VAL_ 2332113057 M2I_Byrack_Enable_IMM24_17 1 "Deactive" 2 "Active" ;
VAL_ 2332113057 M2I_Byrack_ReVeEnable_IMM24_17 0 "invalid" 1 "Read SW-Version" 2 "Read HW-Version" 3 "Barcode" ;
VAL_ 2332113058 M2I_Byrack_Enable_IMM24_18 1 "Deactive" 2 "Active" ;
VAL_ 2332113058 M2I_Byrack_ReVeEnable_IMM24_18 0 "invalid" 1 "Read SW-Version" 2 "Read HW-Version" 3 "Barcode" ;
VAL_ 2332113059 M2I_Byrack_Enable_IMM24_19 1 "Deactive" 2 "Active" ;
VAL_ 2332113059 M2I_Byrack_ReVeEnable_IMM24_19 0 "invalid" 1 "Read SW-Version" 2 "Read HW-Version" 3 "Barcode" ;
VAL_ 2332113060 M2I_Byrack_Enable_IMM24_20 1 "Deactive" 2 "Active" ;
VAL_ 2332113060 M2I_Byrack_ReVeEnable_IMM24_20 0 "invalid" 1 "Read SW-Version" 2 "Read HW-Version" 3 "Barcode" ;
VAL_ 2332113061 M2I_Byrack_Enable_IMM24_21 1 "Deactive" 2 "Active" ;
VAL_ 2332113061 M2I_Byrack_ReVeEnable_IMM24_21 0 "invalid" 1 "Read SW-Version" 2 "Read HW-Version" 3 "Barcode" ;
VAL_ 2332113062 M2I_Byrack_Enable_IMM24_22 1 "Deactive" 2 "Active" ;
VAL_ 2332113062 M2I_Byrack_ReVeEnable_IMM24_22 0 "invalid" 1 "Read SW-Version" 2 "Read HW-Version" 3 "Barcode" ;
VAL_ 2332113063 M2I_Byrack_Enable_IMM24_23 1 "Deactive" 2 "Active" ;
VAL_ 2332113063 M2I_Byrack_ReVeEnable_IMM24_23 0 "invalid" 1 "Read SW-Version" 2 "Read HW-Version" 3 "Barcode" ;
VAL_ 2332113064 M2I_Byrack_Enable_IMM24_24 1 "Deactive" 2 "Active" ;
VAL_ 2332113064 M2I_Byrack_ReVeEnable_IMM24_24 0 "invalid" 1 "Read SW-Version" 2 "Read HW-Version" 3 "Barcode" ;
VAL_ 2332113065 M2I_Byrack_Enable_IMM24_25 1 "Deactive" 2 "Active" ;
VAL_ 2332113065 M2I_Byrack_ReVeEnable_IMM24_25 0 "invalid" 1 "Read SW-Version" 2 "Read HW-Version" 3 "Barcode" ;
VAL_ 2332113066 M2I_Byrack_Enable_IMM24_26 1 "Deactive" 2 "Active" ;
VAL_ 2332113066 M2I_Byrack_ReVeEnable_IMM24_26 0 "invalid" 1 "Read SW-Version" 2 "Read HW-Version" 3 "Barcode" ;
VAL_ 2332113067 M2I_Byrack_Enable_IMM24_27 1 "Deactive" 2 "Active" ;
VAL_ 2332113067 M2I_Byrack_ReVeEnable_IMM24_27 0 "invalid" 1 "Read SW-Version" 2 "Read HW-Version" 3 "Barcode" ;
VAL_ 2332113068 M2I_Byrack_Enable_IMM24_28 1 "Deactive" 2 "Active" ;
VAL_ 2332113068 M2I_Byrack_ReVeEnable_IMM24_28 0 "invalid" 1 "Read SW-Version" 2 "Read HW-Version" 3 "Barcode" ;
VAL_ 2332113069 M2I_Byrack_Enable_IMM24_29 1 "Deactive" 2 "Active" ;
VAL_ 2332113069 M2I_Byrack_ReVeEnable_IMM24_29 0 "invalid" 1 "Read SW-Version" 2 "Read HW-Version" 3 "Barcode" ;
VAL_ 2332113070 M2I_Byrack_Enable_IMM24_30 1 "Deactive" 2 "Active" ;
VAL_ 2332113070 M2I_Byrack_ReVeEnable_IMM24_30 0 "invalid" 1 "Read SW-Version" 2 "Read HW-Version" 3 "Barcode" ;
VAL_ 2332113071 M2I_Byrack_Enable_IMM24_31 1 "Deactive" 2 "Active" ;
VAL_ 2332113071 M2I_Byrack_ReVeEnable_IMM24_31 0 "invalid" 1 "Read SW-Version" 2 "Read HW-Version" 3 "Barcode" ;
VAL_ 2332113297 M2I_Byrack_Enable_IMM25_01 1 "Deactive" 2 "Active" ;
VAL_ 2332113297 M2I_Byrack_ReVeEnable_IMM25_01 0 "invalid" 1 "Read SW-Version" 2 "Read HW-Version" 3 "Barcode" ;
VAL_ 2332113298 M2I_Byrack_Enable_IMM25_02 1 "Deactive" 2 "Active" ;
VAL_ 2332113298 M2I_Byrack_ReVeEnable_IMM25_02 0 "invalid" 1 "Read SW-Version" 2 "Read HW-Version" 3 "Barcode" ;
VAL_ 2332113299 M2I_Byrack_Enable_IMM25_03 1 "Deactive" 2 "Active" ;
VAL_ 2332113299 M2I_Byrack_ReVeEnable_IMM25_03 0 "invalid" 1 "Read SW-Version" 2 "Read HW-Version" 3 "Barcode" ;
VAL_ 2332113300 M2I_Byrack_Enable_IMM25_04 1 "Deactive" 2 "Active" ;
VAL_ 2332113300 M2I_Byrack_ReVeEnable_IMM25_04 0 "invalid" 1 "Read SW-Version" 2 "Read HW-Version" 3 "Barcode" ;
VAL_ 2332113301 M2I_Byrack_Enable_IMM25_05 1 "Deactive" 2 "Active" ;
VAL_ 2332113301 M2I_Byrack_ReVeEnable_IMM25_05 0 "invalid" 1 "Read SW-Version" 2 "Read HW-Version" 3 "Barcode" ;
VAL_ 2332113302 M2I_Byrack_Enable_IMM25_06 1 "Deactive" 2 "Active" ;
VAL_ 2332113302 M2I_Byrack_ReVeEnable_IMM25_06 0 "invalid" 1 "Read SW-Version" 2 "Read HW-Version" 3 "Barcode" ;
VAL_ 2332113303 M2I_Byrack_Enable_IMM25_07 1 "Deactive" 2 "Active" ;
VAL_ 2332113303 M2I_Byrack_ReVeEnable_IMM25_07 0 "invalid" 1 "Read SW-Version" 2 "Read HW-Version" 3 "Barcode" ;
VAL_ 2332113304 M2I_Byrack_Enable_IMM25_08 1 "Deactive" 2 "Active" ;
VAL_ 2332113304 M2I_Byrack_ReVeEnable_IMM25_08 0 "invalid" 1 "Read SW-Version" 2 "Read HW-Version" 3 "Barcode" ;
VAL_ 2332113305 M2I_Byrack_Enable_IMM25_09 1 "Deactive" 2 "Active" ;
VAL_ 2332113305 M2I_Byrack_ReVeEnable_IMM25_09 0 "invalid" 1 "Read SW-Version" 2 "Read HW-Version" 3 "Barcode" ;
VAL_ 2332113306 M2I_Byrack_Enable_IMM25_10 1 "Deactive" 2 "Active" ;
VAL_ 2332113306 M2I_Byrack_ReVeEnable_IMM25_10 0 "invalid" 1 "Read SW-Version" 2 "Read HW-Version" 3 "Barcode" ;
VAL_ 2332113307 M2I_Byrack_Enable_IMM25_11 1 "Deactive" 2 "Active" ;
VAL_ 2332113307 M2I_Byrack_ReVeEnable_IMM25_11 0 "invalid" 1 "Read SW-Version" 2 "Read HW-Version" 3 "Barcode" ;
VAL_ 2332113308 M2I_Byrack_Enable_IMM25_12 1 "Deactive" 2 "Active" ;
VAL_ 2332113308 M2I_Byrack_ReVeEnable_IMM25_12 0 "invalid" 1 "Read SW-Version" 2 "Read HW-Version" 3 "Barcode" ;
VAL_ 2332113309 M2I_Byrack_Enable_IMM25_13 1 "Deactive" 2 "Active" ;
VAL_ 2332113309 M2I_Byrack_ReVeEnable_IMM25_13 0 "invalid" 1 "Read SW-Version" 2 "Read HW-Version" 3 "Barcode" ;
VAL_ 2332113310 M2I_Byrack_Enable_IMM25_14 1 "Deactive" 2 "Active" ;
VAL_ 2332113310 M2I_Byrack_ReVeEnable_IMM25_14 0 "invalid" 1 "Read SW-Version" 2 "Read HW-Version" 3 "Barcode" ;
VAL_ 2332113311 M2I_Byrack_Enable_IMM25_15 1 "Deactive" 2 "Active" ;
VAL_ 2332113311 M2I_Byrack_ReVeEnable_IMM25_15 0 "invalid" 1 "Read SW-Version" 2 "Read HW-Version" 3 "Barcode" ;
VAL_ 2332113312 M2I_Byrack_Enable_IMM25_16 1 "Deactive" 2 "Active" ;
VAL_ 2332113312 M2I_Byrack_ReVeEnable_IMM25_16 0 "invalid" 1 "Read SW-Version" 2 "Read HW-Version" 3 "Barcode" ;
VAL_ 2332113313 M2I_Byrack_Enable_IMM25_17 1 "Deactive" 2 "Active" ;
VAL_ 2332113313 M2I_Byrack_ReVeEnable_IMM25_17 0 "invalid" 1 "Read SW-Version" 2 "Read HW-Version" 3 "Barcode" ;
VAL_ 2332113314 M2I_Byrack_Enable_IMM25_18 1 "Deactive" 2 "Active" ;
VAL_ 2332113314 M2I_Byrack_ReVeEnable_IMM25_18 0 "invalid" 1 "Read SW-Version" 2 "Read HW-Version" 3 "Barcode" ;
VAL_ 2332113315 M2I_Byrack_Enable_IMM25_19 1 "Deactive" 2 "Active" ;
VAL_ 2332113315 M2I_Byrack_ReVeEnable_IMM25_19 0 "invalid" 1 "Read SW-Version" 2 "Read HW-Version" 3 "Barcode" ;
VAL_ 2332113316 M2I_Byrack_Enable_IMM25_20 1 "Deactive" 2 "Active" ;
VAL_ 2332113316 M2I_Byrack_ReVeEnable_IMM25_20 0 "invalid" 1 "Read SW-Version" 2 "Read HW-Version" 3 "Barcode" ;
VAL_ 2332113317 M2I_Byrack_Enable_IMM25_21 1 "Deactive" 2 "Active" ;
VAL_ 2332113317 M2I_Byrack_ReVeEnable_IMM25_21 0 "invalid" 1 "Read SW-Version" 2 "Read HW-Version" 3 "Barcode" ;
VAL_ 2332113318 M2I_Byrack_Enable_IMM25_22 1 "Deactive" 2 "Active" ;
VAL_ 2332113318 M2I_Byrack_ReVeEnable_IMM25_22 0 "invalid" 1 "Read SW-Version" 2 "Read HW-Version" 3 "Barcode" ;
VAL_ 2332113319 M2I_Byrack_Enable_IMM25_23 1 "Deactive" 2 "Active" ;
VAL_ 2332113319 M2I_Byrack_ReVeEnable_IMM25_23 0 "invalid" 1 "Read SW-Version" 2 "Read HW-Version" 3 "Barcode" ;
VAL_ 2332113320 M2I_Byrack_Enable_IMM25_24 1 "Deactive" 2 "Active" ;
VAL_ 2332113320 M2I_Byrack_ReVeEnable_IMM25_24 0 "invalid" 1 "Read SW-Version" 2 "Read HW-Version" 3 "Barcode" ;
VAL_ 2332113321 M2I_Byrack_Enable_IMM25_25 1 "Deactive" 2 "Active" ;
VAL_ 2332113321 M2I_Byrack_ReVeEnable_IMM25_25 0 "invalid" 1 "Read SW-Version" 2 "Read HW-Version" 3 "Barcode" ;
VAL_ 2332113322 M2I_Byrack_Enable_IMM25_26 1 "Deactive" 2 "Active" ;
VAL_ 2332113322 M2I_Byrack_ReVeEnable_IMM25_26 0 "invalid" 1 "Read SW-Version" 2 "Read HW-Version" 3 "Barcode" ;
VAL_ 2332113323 M2I_Byrack_Enable_IMM25_27 1 "Deactive" 2 "Active" ;
VAL_ 2332113323 M2I_Byrack_ReVeEnable_IMM25_27 0 "invalid" 1 "Read SW-Version" 2 "Read HW-Version" 3 "Barcode" ;
VAL_ 2332113324 M2I_Byrack_Enable_IMM25_28 1 "Deactive" 2 "Active" ;
VAL_ 2332113324 M2I_Byrack_ReVeEnable_IMM25_28 0 "invalid" 1 "Read SW-Version" 2 "Read HW-Version" 3 "Barcode" ;
VAL_ 2332113325 M2I_Byrack_Enable_IMM25_29 1 "Deactive" 2 "Active" ;
VAL_ 2332113325 M2I_Byrack_ReVeEnable_IMM25_29 0 "invalid" 1 "Read SW-Version" 2 "Read HW-Version" 3 "Barcode" ;
VAL_ 2332113326 M2I_Byrack_Enable_IMM25_30 1 "Deactive" 2 "Active" ;
VAL_ 2332113326 M2I_Byrack_ReVeEnable_IMM25_30 0 "invalid" 1 "Read SW-Version" 2 "Read HW-Version" 3 "Barcode" ;
VAL_ 2332113327 M2I_Byrack_Enable_IMM25_31 1 "Deactive" 2 "Active" ;
VAL_ 2332113327 M2I_Byrack_ReVeEnable_IMM25_31 0 "invalid" 1 "Read SW-Version" 2 "Read HW-Version" 3 "Barcode" ;
VAL_ 2332113553 M2I_Byrack_Enable_IMM26_01 1 "Deactive" 2 "Active" ;
VAL_ 2332113553 M2I_Byrack_ReVeEnable_IMM26_01 0 "invalid" 1 "Read SW-Version" 2 "Read HW-Version" 3 "Barcode" ;
VAL_ 2332113554 M2I_Byrack_Enable_IMM26_02 1 "Deactive" 2 "Active" ;
VAL_ 2332113554 M2I_Byrack_ReVeEnable_IMM26_02 0 "invalid" 1 "Read SW-Version" 2 "Read HW-Version" 3 "Barcode" ;
VAL_ 2332113555 M2I_Byrack_Enable_IMM26_03 1 "Deactive" 2 "Active" ;
VAL_ 2332113555 M2I_Byrack_ReVeEnable_IMM26_03 0 "invalid" 1 "Read SW-Version" 2 "Read HW-Version" 3 "Barcode" ;
VAL_ 2332113556 M2I_Byrack_Enable_IMM26_04 1 "Deactive" 2 "Active" ;
VAL_ 2332113556 M2I_Byrack_ReVeEnable_IMM26_04 0 "invalid" 1 "Read SW-Version" 2 "Read HW-Version" 3 "Barcode" ;
VAL_ 2332113557 M2I_Byrack_Enable_IMM26_05 1 "Deactive" 2 "Active" ;
VAL_ 2332113557 M2I_Byrack_ReVeEnable_IMM26_05 0 "invalid" 1 "Read SW-Version" 2 "Read HW-Version" 3 "Barcode" ;
VAL_ 2332113558 M2I_Byrack_Enable_IMM26_06 1 "Deactive" 2 "Active" ;
VAL_ 2332113558 M2I_Byrack_ReVeEnable_IMM26_06 0 "invalid" 1 "Read SW-Version" 2 "Read HW-Version" 3 "Barcode" ;
VAL_ 2332113559 M2I_Byrack_Enable_IMM26_07 1 "Deactive" 2 "Active" ;
VAL_ 2332113559 M2I_Byrack_ReVeEnable_IMM26_07 0 "invalid" 1 "Read SW-Version" 2 "Read HW-Version" 3 "Barcode" ;
VAL_ 2332113560 M2I_Byrack_Enable_IMM26_08 1 "Deactive" 2 "Active" ;
VAL_ 2332113560 M2I_Byrack_ReVeEnable_IMM26_08 0 "invalid" 1 "Read SW-Version" 2 "Read HW-Version" 3 "Barcode" ;
VAL_ 2332113561 M2I_Byrack_Enable_IMM26_09 1 "Deactive" 2 "Active" ;
VAL_ 2332113561 M2I_Byrack_ReVeEnable_IMM26_09 0 "invalid" 1 "Read SW-Version" 2 "Read HW-Version" 3 "Barcode" ;
VAL_ 2332113562 M2I_Byrack_Enable_IMM26_10 1 "Deactive" 2 "Active" ;
VAL_ 2332113562 M2I_Byrack_ReVeEnable_IMM26_10 0 "invalid" 1 "Read SW-Version" 2 "Read HW-Version" 3 "Barcode" ;
VAL_ 2332113563 M2I_Byrack_Enable_IMM26_11 1 "Deactive" 2 "Active" ;
VAL_ 2332113563 M2I_Byrack_ReVeEnable_IMM26_11 0 "invalid" 1 "Read SW-Version" 2 "Read HW-Version" 3 "Barcode" ;
VAL_ 2332113564 M2I_Byrack_Enable_IMM26_12 1 "Deactive" 2 "Active" ;
VAL_ 2332113564 M2I_Byrack_ReVeEnable_IMM26_12 0 "invalid" 1 "Read SW-Version" 2 "Read HW-Version" 3 "Barcode" ;
VAL_ 2332113565 M2I_Byrack_Enable_IMM26_13 1 "Deactive" 2 "Active" ;
VAL_ 2332113565 M2I_Byrack_ReVeEnable_IMM26_13 0 "invalid" 1 "Read SW-Version" 2 "Read HW-Version" 3 "Barcode" ;
VAL_ 2332113566 M2I_Byrack_Enable_IMM26_14 1 "Deactive" 2 "Active" ;
VAL_ 2332113566 M2I_Byrack_ReVeEnable_IMM26_14 0 "invalid" 1 "Read SW-Version" 2 "Read HW-Version" 3 "Barcode" ;
VAL_ 2332113567 M2I_Byrack_Enable_IMM26_15 1 "Deactive" 2 "Active" ;
VAL_ 2332113567 M2I_Byrack_ReVeEnable_IMM26_15 0 "invalid" 1 "Read SW-Version" 2 "Read HW-Version" 3 "Barcode" ;
VAL_ 2332113568 M2I_Byrack_Enable_IMM26_16 1 "Deactive" 2 "Active" ;
VAL_ 2332113568 M2I_Byrack_ReVeEnable_IMM26_16 0 "invalid" 1 "Read SW-Version" 2 "Read HW-Version" 3 "Barcode" ;
VAL_ 2332113569 M2I_Byrack_Enable_IMM26_17 1 "Deactive" 2 "Active" ;
VAL_ 2332113569 M2I_Byrack_ReVeEnable_IMM26_17 0 "invalid" 1 "Read SW-Version" 2 "Read HW-Version" 3 "Barcode" ;
VAL_ 2332113570 M2I_Byrack_Enable_IMM26_18 1 "Deactive" 2 "Active" ;
VAL_ 2332113570 M2I_Byrack_ReVeEnable_IMM26_18 0 "invalid" 1 "Read SW-Version" 2 "Read HW-Version" 3 "Barcode" ;
VAL_ 2332113571 M2I_Byrack_Enable_IMM26_19 1 "Deactive" 2 "Active" ;
VAL_ 2332113571 M2I_Byrack_ReVeEnable_IMM26_19 0 "invalid" 1 "Read SW-Version" 2 "Read HW-Version" 3 "Barcode" ;
VAL_ 2332113572 M2I_Byrack_Enable_IMM26_20 1 "Deactive" 2 "Active" ;
VAL_ 2332113572 M2I_Byrack_ReVeEnable_IMM26_20 0 "invalid" 1 "Read SW-Version" 2 "Read HW-Version" 3 "Barcode" ;
VAL_ 2332113573 M2I_Byrack_Enable_IMM26_21 1 "Deactive" 2 "Active" ;
VAL_ 2332113573 M2I_Byrack_ReVeEnable_IMM26_21 0 "invalid" 1 "Read SW-Version" 2 "Read HW-Version" 3 "Barcode" ;
VAL_ 2332113574 M2I_Byrack_Enable_IMM26_22 1 "Deactive" 2 "Active" ;
VAL_ 2332113574 M2I_Byrack_ReVeEnable_IMM26_22 0 "invalid" 1 "Read SW-Version" 2 "Read HW-Version" 3 "Barcode" ;
VAL_ 2332113575 M2I_Byrack_Enable_IMM26_23 1 "Deactive" 2 "Active" ;
VAL_ 2332113575 M2I_Byrack_ReVeEnable_IMM26_23 0 "invalid" 1 "Read SW-Version" 2 "Read HW-Version" 3 "Barcode" ;
VAL_ 2332113576 M2I_Byrack_Enable_IMM26_24 1 "Deactive" 2 "Active" ;
VAL_ 2332113576 M2I_Byrack_ReVeEnable_IMM26_24 0 "invalid" 1 "Read SW-Version" 2 "Read HW-Version" 3 "Barcode" ;
VAL_ 2332113577 M2I_Byrack_Enable_IMM26_25 1 "Deactive" 2 "Active" ;
VAL_ 2332113577 M2I_Byrack_ReVeEnable_IMM26_25 0 "invalid" 1 "Read SW-Version" 2 "Read HW-Version" 3 "Barcode" ;
VAL_ 2332113578 M2I_Byrack_Enable_IMM26_26 1 "Deactive" 2 "Active" ;
VAL_ 2332113578 M2I_Byrack_ReVeEnable_IMM26_26 0 "invalid" 1 "Read SW-Version" 2 "Read HW-Version" 3 "Barcode" ;
VERSION ""

NS_ :

BS_:

BU_: MBMU PC SBMU IMM ETH DCDC LEMS

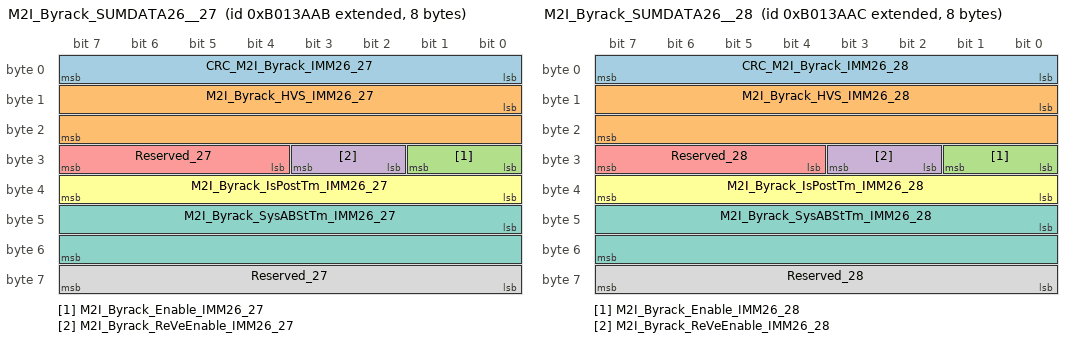
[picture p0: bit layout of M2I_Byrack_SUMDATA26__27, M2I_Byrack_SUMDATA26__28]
BO_ 2332113579 M2I_Byrack_SUMDATA26__27: 8 MBMU
 SG_ CRC_M2I_Byrack_IMM26_27 : 0|8@1+ (1,0) [0|255] ""  IMM
 SG_ M2I_Byrack_HVS_IMM26_27 : 8|16@1+ (0.1,0) [0|6553.5] "v"  IMM
 SG_ M2I_Byrack_Enable_IMM26_27 : 24|2@1+ (1,0) [0|3] ""  IMM
 SG_ M2I_Byrack_ReVeEnable_IMM26_27 : 26|2@1+ (1,0) [0|3] ""  IMM
 SG_ Reserved_27 : 28|4@1+ (1,0) [0|15] ""  IMM
 SG_ M2I_Byrack_IsPostTm_IMM26_27 : 32|8@1+ (0.01,0) [0|2.55] "s"  IMM
 SG_ M2I_Byrack_SysABStTm_IMM26_27 : 40|16@1+ (0.01,0) [0|655.35] "s"  IMM
 SG_ Reserved_27 : 56|8@1+ (1,0) [0|255] ""  IMM

BO_ 2332113580 M2I_Byrack_SUMDATA26__28: 8 MBMU
 SG_ CRC_M2I_Byrack_IMM26_28 : 0|8@1+ (1,0) [0|255] ""  IMM
 SG_ M2I_Byrack_HVS_IMM26_28 : 8|16@1+ (0.1,0) [0|6553.5] "v"  IMM
 SG_ M2I_Byrack_Enable_IMM26_28 : 24|2@1+ (1,0) [0|3] ""  IMM
 SG_ M2I_Byrack_ReVeEnable_IMM26_28 : 26|2@1+ (1,0) [0|3] ""  IMM
 SG_ Reserved_28 : 28|4@1+ (1,0) [0|15] ""  IMM
 SG_ M2I_Byrack_IsPostTm_IMM26_28 : 32|8@1+ (0.01,0) [0|2.55] "s"  IMM
 SG_ M2I_Byrack_SysABStTm_IMM26_28 : 40|16@1+ (0.01,0) [0|655.35] "s"  IMM
 SG_ Reserved_28 : 56|8@1+ (1,0) [0|255] ""  IMM

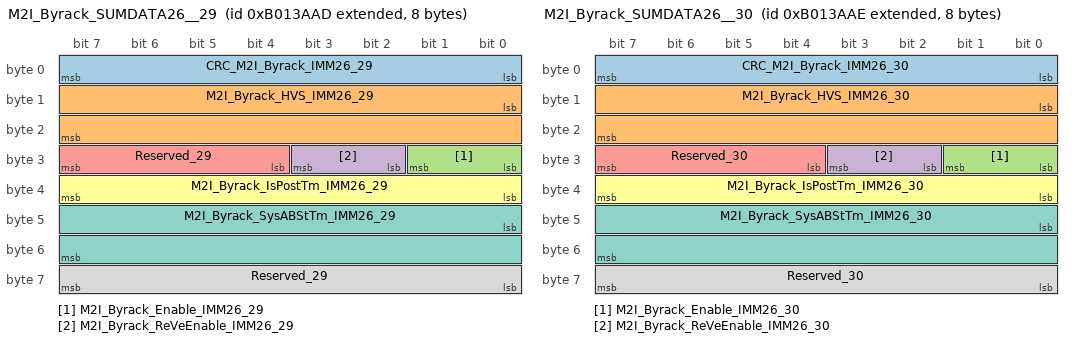
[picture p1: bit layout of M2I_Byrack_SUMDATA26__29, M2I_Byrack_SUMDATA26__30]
BO_ 2332113581 M2I_Byrack_SUMDATA26__29: 8 MBMU
 SG_ CRC_M2I_Byrack_IMM26_29 : 0|8@1+ (1,0) [0|255] ""  IMM
 SG_ M2I_Byrack_HVS_IMM26_29 : 8|16@1+ (0.1,0) [0|6553.5] "v"  IMM
 SG_ M2I_Byrack_Enable_IMM26_29 : 24|2@1+ (1,0) [0|3] ""  IMM
 SG_ M2I_Byrack_ReVeEnable_IMM26_29 : 26|2@1+ (1,0) [0|3] ""  IMM
 SG_ Reserved_29 : 28|4@1+ (1,0) [0|15] ""  IMM
 SG_ M2I_Byrack_IsPostTm_IMM26_29 : 32|8@1+ (0.01,0) [0|2.55] "s"  IMM
 SG_ M2I_Byrack_SysABStTm_IMM26_29 : 40|16@1+ (0.01,0) [0|655.35] "s"  IMM
 SG_ Reserved_29 : 56|8@1+ (1,0) [0|255] ""  IMM

BO_ 2332113582 M2I_Byrack_SUMDATA26__30: 8 MBMU
 SG_ CRC_M2I_Byrack_IMM26_30 : 0|8@1+ (1,0) [0|255] ""  IMM
 SG_ M2I_Byrack_HVS_IMM26_30 : 8|16@1+ (0.1,0) [0|6553.5] "v"  IMM
 SG_ M2I_Byrack_Enable_IMM26_30 : 24|2@1+ (1,0) [0|3] ""  IMM
 SG_ M2I_Byrack_ReVeEnable_IMM26_30 : 26|2@1+ (1,0) [0|3] ""  IMM
 SG_ Reserved_30 : 28|4@1+ (1,0) [0|15] ""  IMM
 SG_ M2I_Byrack_IsPostTm_IMM26_30 : 32|8@1+ (0.01,0) [0|2.55] "s"  IMM
 SG_ M2I_Byrack_SysABStTm_IMM26_30 : 40|16@1+ (0.01,0) [0|655.35] "s"  IMM
 SG_ Reserved_30 : 56|8@1+ (1,0) [0|255] ""  IMM

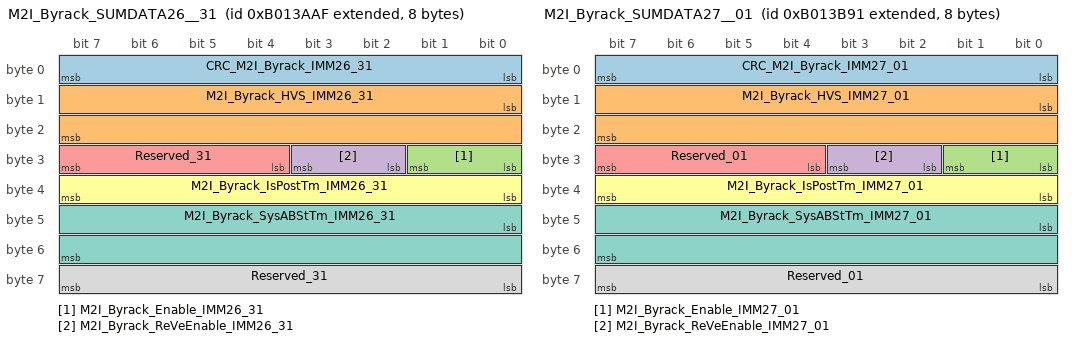
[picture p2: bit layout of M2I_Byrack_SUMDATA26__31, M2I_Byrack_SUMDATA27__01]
BO_ 2332113583 M2I_Byrack_SUMDATA26__31: 8 MBMU
 SG_ CRC_M2I_Byrack_IMM26_31 : 0|8@1+ (1,0) [0|255] ""  IMM
 SG_ M2I_Byrack_HVS_IMM26_31 : 8|16@1+ (0.1,0) [0|6553.5] "v"  IMM
 SG_ M2I_Byrack_Enable_IMM26_31 : 24|2@1+ (1,0) [0|3] ""  IMM
 SG_ M2I_Byrack_ReVeEnable_IMM26_31 : 26|2@1+ (1,0) [0|3] ""  IMM
 SG_ Reserved_31 : 28|4@1+ (1,0) [0|15] ""  IMM
 SG_ M2I_Byrack_IsPostTm_IMM26_31 : 32|8@1+ (0.01,0) [0|2.55] "s"  IMM
 SG_ M2I_Byrack_SysABStTm_IMM26_31 : 40|16@1+ (0.01,0) [0|655.35] "s"  IMM
 SG_ Reserved_31 : 56|8@1+ (1,0) [0|255] ""  IMM

BO_ 2332113809 M2I_Byrack_SUMDATA27__01: 8 MBMU
 SG_ CRC_M2I_Byrack_IMM27_01 : 0|8@1+ (1,0) [0|255] ""  IMM
 SG_ M2I_Byrack_HVS_IMM27_01 : 8|16@1+ (0.1,0) [0|6553.5] "v"  IMM
 SG_ M2I_Byrack_Enable_IMM27_01 : 24|2@1+ (1,0) [0|3] ""  IMM
 SG_ M2I_Byrack_ReVeEnable_IMM27_01 : 26|2@1+ (1,0) [0|3] ""  IMM
 SG_ Reserved_01 : 28|4@1+ (1,0) [0|15] ""  IMM
 SG_ M2I_Byrack_IsPostTm_IMM27_01 : 32|8@1+ (0.01,0) [0|2.55] "s"  IMM
 SG_ M2I_Byrack_SysABStTm_IMM27_01 : 40|16@1+ (0.01,0) [0|655.35] "s"  IMM
 SG_ Reserved_01 : 56|8@1+ (1,0) [0|255] ""  IMM

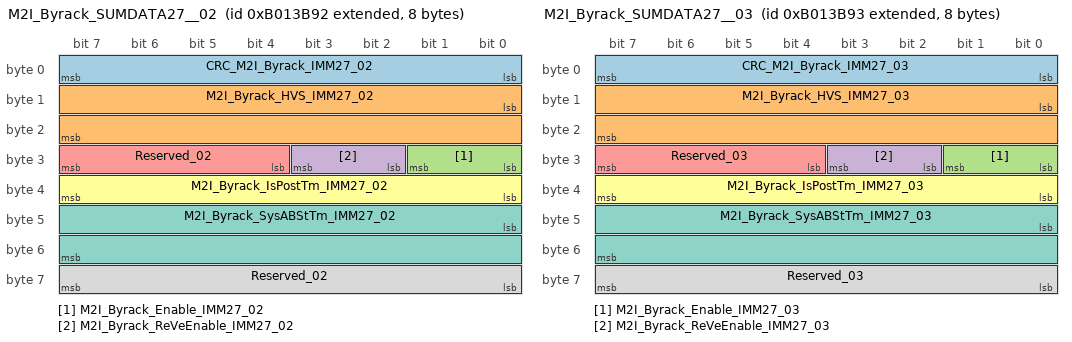
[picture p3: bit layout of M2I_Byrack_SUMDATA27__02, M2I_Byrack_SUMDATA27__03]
BO_ 2332113810 M2I_Byrack_SUMDATA27__02: 8 MBMU
 SG_ CRC_M2I_Byrack_IMM27_02 : 0|8@1+ (1,0) [0|255] ""  IMM
 SG_ M2I_Byrack_HVS_IMM27_02 : 8|16@1+ (0.1,0) [0|6553.5] "v"  IMM
 SG_ M2I_Byrack_Enable_IMM27_02 : 24|2@1+ (1,0) [0|3] ""  IMM
 SG_ M2I_Byrack_ReVeEnable_IMM27_02 : 26|2@1+ (1,0) [0|3] ""  IMM
 SG_ Reserved_02 : 28|4@1+ (1,0) [0|15] ""  IMM
 SG_ M2I_Byrack_IsPostTm_IMM27_02 : 32|8@1+ (0.01,0) [0|2.55] "s"  IMM
 SG_ M2I_Byrack_SysABStTm_IMM27_02 : 40|16@1+ (0.01,0) [0|655.35] "s"  IMM
 SG_ Reserved_02 : 56|8@1+ (1,0) [0|255] ""  IMM

BO_ 2332113811 M2I_Byrack_SUMDATA27__03: 8 MBMU
 SG_ CRC_M2I_Byrack_IMM27_03 : 0|8@1+ (1,0) [0|255] ""  IMM
 SG_ M2I_Byrack_HVS_IMM27_03 : 8|16@1+ (0.1,0) [0|6553.5] "v"  IMM
 SG_ M2I_Byrack_Enable_IMM27_03 : 24|2@1+ (1,0) [0|3] ""  IMM
 SG_ M2I_Byrack_ReVeEnable_IMM27_03 : 26|2@1+ (1,0) [0|3] ""  IMM
 SG_ Reserved_03 : 28|4@1+ (1,0) [0|15] ""  IMM
 SG_ M2I_Byrack_IsPostTm_IMM27_03 : 32|8@1+ (0.01,0) [0|2.55] "s"  IMM
 SG_ M2I_Byrack_SysABStTm_IMM27_03 : 40|16@1+ (0.01,0) [0|655.35] "s"  IMM
 SG_ Reserved_03 : 56|8@1+ (1,0) [0|255] ""  IMM

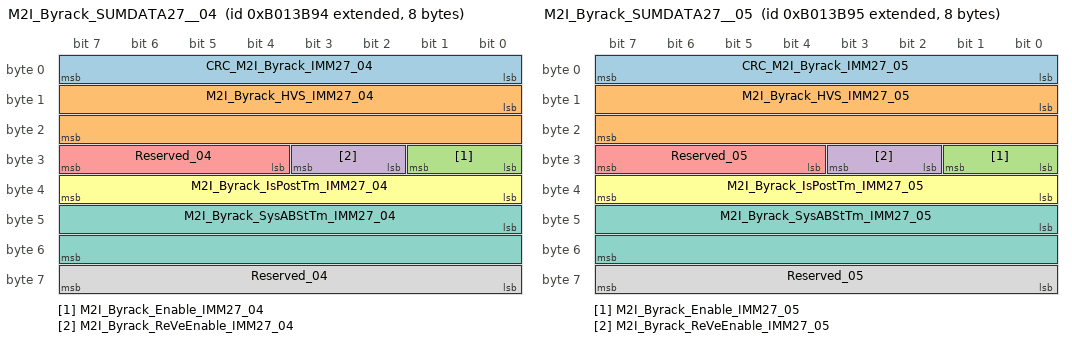
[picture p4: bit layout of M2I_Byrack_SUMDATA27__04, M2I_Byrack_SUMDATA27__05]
BO_ 2332113812 M2I_Byrack_SUMDATA27__04: 8 MBMU
 SG_ CRC_M2I_Byrack_IMM27_04 : 0|8@1+ (1,0) [0|255] ""  IMM
 SG_ M2I_Byrack_HVS_IMM27_04 : 8|16@1+ (0.1,0) [0|6553.5] "v"  IMM
 SG_ M2I_Byrack_Enable_IMM27_04 : 24|2@1+ (1,0) [0|3] ""  IMM
 SG_ M2I_Byrack_ReVeEnable_IMM27_04 : 26|2@1+ (1,0) [0|3] ""  IMM
 SG_ Reserved_04 : 28|4@1+ (1,0) [0|15] ""  IMM
 SG_ M2I_Byrack_IsPostTm_IMM27_04 : 32|8@1+ (0.01,0) [0|2.55] "s"  IMM
 SG_ M2I_Byrack_SysABStTm_IMM27_04 : 40|16@1+ (0.01,0) [0|655.35] "s"  IMM
 SG_ Reserved_04 : 56|8@1+ (1,0) [0|255] ""  IMM

BO_ 2332113813 M2I_Byrack_SUMDATA27__05: 8 MBMU
 SG_ CRC_M2I_Byrack_IMM27_05 : 0|8@1+ (1,0) [0|255] ""  IMM
 SG_ M2I_Byrack_HVS_IMM27_05 : 8|16@1+ (0.1,0) [0|6553.5] "v"  IMM
 SG_ M2I_Byrack_Enable_IMM27_05 : 24|2@1+ (1,0) [0|3] ""  IMM
 SG_ M2I_Byrack_ReVeEnable_IMM27_05 : 26|2@1+ (1,0) [0|3] ""  IMM
 SG_ Reserved_05 : 28|4@1+ (1,0) [0|15] ""  IMM
 SG_ M2I_Byrack_IsPostTm_IMM27_05 : 32|8@1+ (0.01,0) [0|2.55] "s"  IMM
 SG_ M2I_Byrack_SysABStTm_IMM27_05 : 40|16@1+ (0.01,0) [0|655.35] "s"  IMM
 SG_ Reserved_05 : 56|8@1+ (1,0) [0|255] ""  IMM

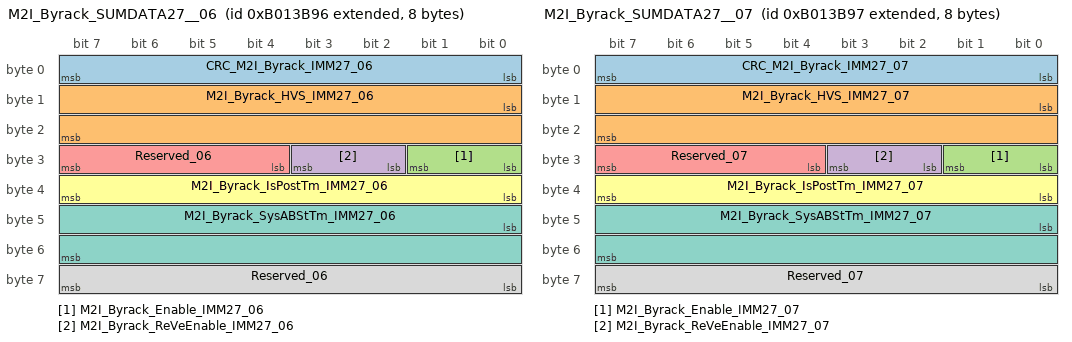
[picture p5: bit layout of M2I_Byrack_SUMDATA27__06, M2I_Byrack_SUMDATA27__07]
BO_ 2332113814 M2I_Byrack_SUMDATA27__06: 8 MBMU
 SG_ CRC_M2I_Byrack_IMM27_06 : 0|8@1+ (1,0) [0|255] ""  IMM
 SG_ M2I_Byrack_HVS_IMM27_06 : 8|16@1+ (0.1,0) [0|6553.5] "v"  IMM
 SG_ M2I_Byrack_Enable_IMM27_06 : 24|2@1+ (1,0) [0|3] ""  IMM
 SG_ M2I_Byrack_ReVeEnable_IMM27_06 : 26|2@1+ (1,0) [0|3] ""  IMM
 SG_ Reserved_06 : 28|4@1+ (1,0) [0|15] ""  IMM
 SG_ M2I_Byrack_IsPostTm_IMM27_06 : 32|8@1+ (0.01,0) [0|2.55] "s"  IMM
 SG_ M2I_Byrack_SysABStTm_IMM27_06 : 40|16@1+ (0.01,0) [0|655.35] "s"  IMM
 SG_ Reserved_06 : 56|8@1+ (1,0) [0|255] ""  IMM

BO_ 2332113815 M2I_Byrack_SUMDATA27__07: 8 MBMU
 SG_ CRC_M2I_Byrack_IMM27_07 : 0|8@1+ (1,0) [0|255] ""  IMM
 SG_ M2I_Byrack_HVS_IMM27_07 : 8|16@1+ (0.1,0) [0|6553.5] "v"  IMM
 SG_ M2I_Byrack_Enable_IMM27_07 : 24|2@1+ (1,0) [0|3] ""  IMM
 SG_ M2I_Byrack_ReVeEnable_IMM27_07 : 26|2@1+ (1,0) [0|3] ""  IMM
 SG_ Reserved_07 : 28|4@1+ (1,0) [0|15] ""  IMM
 SG_ M2I_Byrack_IsPostTm_IMM27_07 : 32|8@1+ (0.01,0) [0|2.55] "s"  IMM
 SG_ M2I_Byrack_SysABStTm_IMM27_07 : 40|16@1+ (0.01,0) [0|655.35] "s"  IMM
 SG_ Reserved_07 : 56|8@1+ (1,0) [0|255] ""  IMM

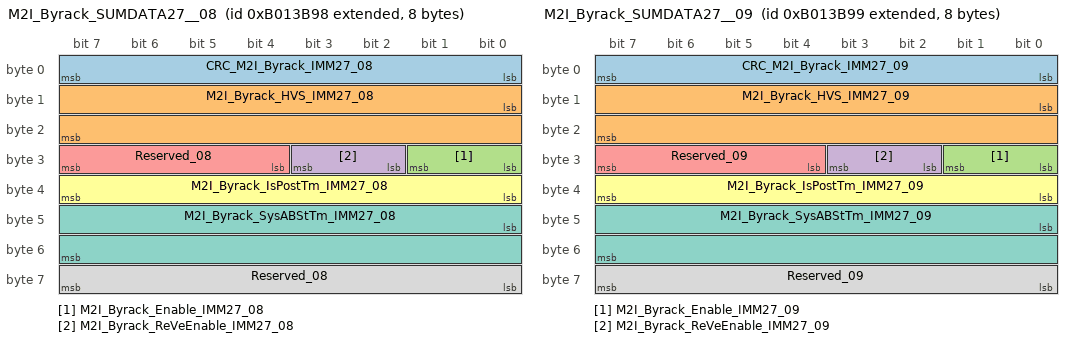
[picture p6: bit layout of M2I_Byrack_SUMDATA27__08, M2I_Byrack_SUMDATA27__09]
BO_ 2332113816 M2I_Byrack_SUMDATA27__08: 8 MBMU
 SG_ CRC_M2I_Byrack_IMM27_08 : 0|8@1+ (1,0) [0|255] ""  IMM
 SG_ M2I_Byrack_HVS_IMM27_08 : 8|16@1+ (0.1,0) [0|6553.5] "v"  IMM
 SG_ M2I_Byrack_Enable_IMM27_08 : 24|2@1+ (1,0) [0|3] ""  IMM
 SG_ M2I_Byrack_ReVeEnable_IMM27_08 : 26|2@1+ (1,0) [0|3] ""  IMM
 SG_ Reserved_08 : 28|4@1+ (1,0) [0|15] ""  IMM
 SG_ M2I_Byrack_IsPostTm_IMM27_08 : 32|8@1+ (0.01,0) [0|2.55] "s"  IMM
 SG_ M2I_Byrack_SysABStTm_IMM27_08 : 40|16@1+ (0.01,0) [0|655.35] "s"  IMM
 SG_ Reserved_08 : 56|8@1+ (1,0) [0|255] ""  IMM

BO_ 2332113817 M2I_Byrack_SUMDATA27__09: 8 MBMU
 SG_ CRC_M2I_Byrack_IMM27_09 : 0|8@1+ (1,0) [0|255] ""  IMM
 SG_ M2I_Byrack_HVS_IMM27_09 : 8|16@1+ (0.1,0) [0|6553.5] "v"  IMM
 SG_ M2I_Byrack_Enable_IMM27_09 : 24|2@1+ (1,0) [0|3] ""  IMM
 SG_ M2I_Byrack_ReVeEnable_IMM27_09 : 26|2@1+ (1,0) [0|3] ""  IMM
 SG_ Reserved_09 : 28|4@1+ (1,0) [0|15] ""  IMM
 SG_ M2I_Byrack_IsPostTm_IMM27_09 : 32|8@1+ (0.01,0) [0|2.55] "s"  IMM
 SG_ M2I_Byrack_SysABStTm_IMM27_09 : 40|16@1+ (0.01,0) [0|655.35] "s"  IMM
 SG_ Reserved_09 : 56|8@1+ (1,0) [0|255] ""  IMM

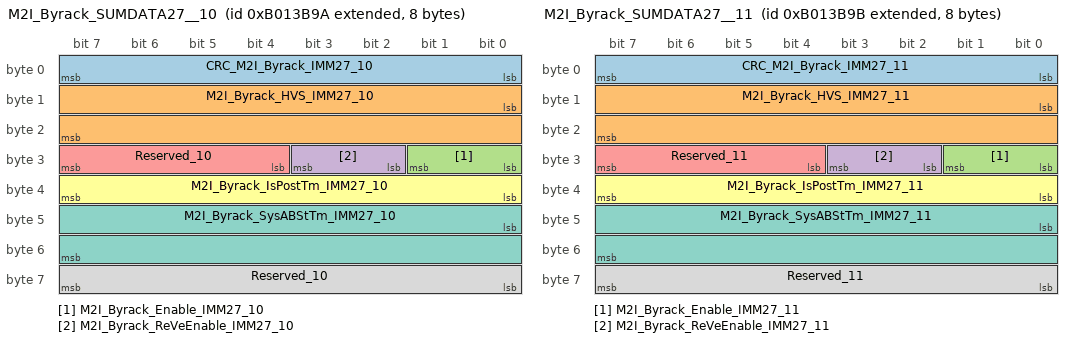
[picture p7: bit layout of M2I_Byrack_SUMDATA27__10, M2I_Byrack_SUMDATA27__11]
BO_ 2332113818 M2I_Byrack_SUMDATA27__10: 8 MBMU
 SG_ CRC_M2I_Byrack_IMM27_10 : 0|8@1+ (1,0) [0|255] ""  IMM
 SG_ M2I_Byrack_HVS_IMM27_10 : 8|16@1+ (0.1,0) [0|6553.5] "v"  IMM
 SG_ M2I_Byrack_Enable_IMM27_10 : 24|2@1+ (1,0) [0|3] ""  IMM
 SG_ M2I_Byrack_ReVeEnable_IMM27_10 : 26|2@1+ (1,0) [0|3] ""  IMM
 SG_ Reserved_10 : 28|4@1+ (1,0) [0|15] ""  IMM
 SG_ M2I_Byrack_IsPostTm_IMM27_10 : 32|8@1+ (0.01,0) [0|2.55] "s"  IMM
 SG_ M2I_Byrack_SysABStTm_IMM27_10 : 40|16@1+ (0.01,0) [0|655.35] "s"  IMM
 SG_ Reserved_10 : 56|8@1+ (1,0) [0|255] ""  IMM

BO_ 2332113819 M2I_Byrack_SUMDATA27__11: 8 MBMU
 SG_ CRC_M2I_Byrack_IMM27_11 : 0|8@1+ (1,0) [0|255] ""  IMM
 SG_ M2I_Byrack_HVS_IMM27_11 : 8|16@1+ (0.1,0) [0|6553.5] "v"  IMM
 SG_ M2I_Byrack_Enable_IMM27_11 : 24|2@1+ (1,0) [0|3] ""  IMM
 SG_ M2I_Byrack_ReVeEnable_IMM27_11 : 26|2@1+ (1,0) [0|3] ""  IMM
 SG_ Reserved_11 : 28|4@1+ (1,0) [0|15] ""  IMM
 SG_ M2I_Byrack_IsPostTm_IMM27_11 : 32|8@1+ (0.01,0) [0|2.55] "s"  IMM
 SG_ M2I_Byrack_SysABStTm_IMM27_11 : 40|16@1+ (0.01,0) [0|655.35] "s"  IMM
 SG_ Reserved_11 : 56|8@1+ (1,0) [0|255] ""  IMM

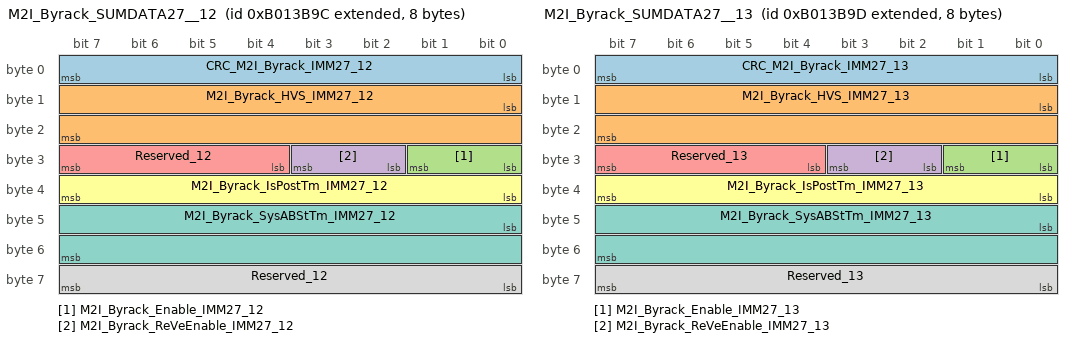
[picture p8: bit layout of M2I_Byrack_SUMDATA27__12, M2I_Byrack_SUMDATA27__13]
BO_ 2332113820 M2I_Byrack_SUMDATA27__12: 8 MBMU
 SG_ CRC_M2I_Byrack_IMM27_12 : 0|8@1+ (1,0) [0|255] ""  IMM
 SG_ M2I_Byrack_HVS_IMM27_12 : 8|16@1+ (0.1,0) [0|6553.5] "v"  IMM
 SG_ M2I_Byrack_Enable_IMM27_12 : 24|2@1+ (1,0) [0|3] ""  IMM
 SG_ M2I_Byrack_ReVeEnable_IMM27_12 : 26|2@1+ (1,0) [0|3] ""  IMM
 SG_ Reserved_12 : 28|4@1+ (1,0) [0|15] ""  IMM
 SG_ M2I_Byrack_IsPostTm_IMM27_12 : 32|8@1+ (0.01,0) [0|2.55] "s"  IMM
 SG_ M2I_Byrack_SysABStTm_IMM27_12 : 40|16@1+ (0.01,0) [0|655.35] "s"  IMM
 SG_ Reserved_12 : 56|8@1+ (1,0) [0|255] ""  IMM

BO_ 2332113821 M2I_Byrack_SUMDATA27__13: 8 MBMU
 SG_ CRC_M2I_Byrack_IMM27_13 : 0|8@1+ (1,0) [0|255] ""  IMM
 SG_ M2I_Byrack_HVS_IMM27_13 : 8|16@1+ (0.1,0) [0|6553.5] "v"  IMM
 SG_ M2I_Byrack_Enable_IMM27_13 : 24|2@1+ (1,0) [0|3] ""  IMM
 SG_ M2I_Byrack_ReVeEnable_IMM27_13 : 26|2@1+ (1,0) [0|3] ""  IMM
 SG_ Reserved_13 : 28|4@1+ (1,0) [0|15] ""  IMM
 SG_ M2I_Byrack_IsPostTm_IMM27_13 : 32|8@1+ (0.01,0) [0|2.55] "s"  IMM
 SG_ M2I_Byrack_SysABStTm_IMM27_13 : 40|16@1+ (0.01,0) [0|655.35] "s"  IMM
 SG_ Reserved_13 : 56|8@1+ (1,0) [0|255] ""  IMM

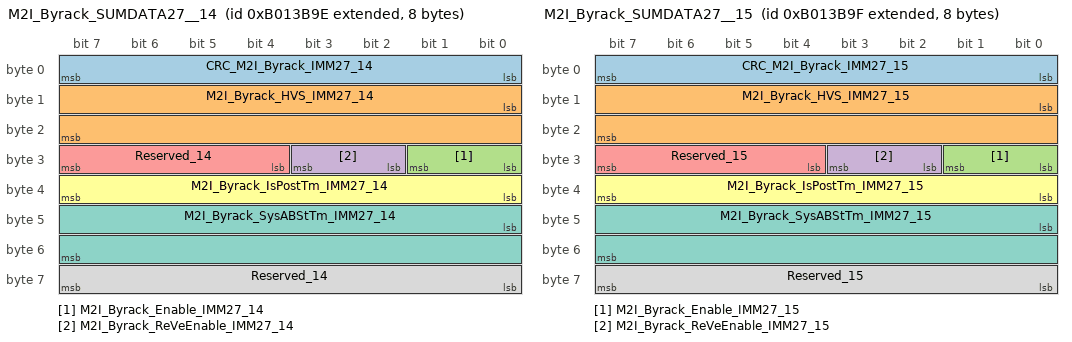
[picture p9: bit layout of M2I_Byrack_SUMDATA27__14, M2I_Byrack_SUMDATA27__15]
BO_ 2332113822 M2I_Byrack_SUMDATA27__14: 8 MBMU
 SG_ CRC_M2I_Byrack_IMM27_14 : 0|8@1+ (1,0) [0|255] ""  IMM
 SG_ M2I_Byrack_HVS_IMM27_14 : 8|16@1+ (0.1,0) [0|6553.5] "v"  IMM
 SG_ M2I_Byrack_Enable_IMM27_14 : 24|2@1+ (1,0) [0|3] ""  IMM
 SG_ M2I_Byrack_ReVeEnable_IMM27_14 : 26|2@1+ (1,0) [0|3] ""  IMM
 SG_ Reserved_14 : 28|4@1+ (1,0) [0|15] ""  IMM
 SG_ M2I_Byrack_IsPostTm_IMM27_14 : 32|8@1+ (0.01,0) [0|2.55] "s"  IMM
 SG_ M2I_Byrack_SysABStTm_IMM27_14 : 40|16@1+ (0.01,0) [0|655.35] "s"  IMM
 SG_ Reserved_14 : 56|8@1+ (1,0) [0|255] ""  IMM

BO_ 2332113823 M2I_Byrack_SUMDATA27__15: 8 MBMU
 SG_ CRC_M2I_Byrack_IMM27_15 : 0|8@1+ (1,0) [0|255] ""  IMM
 SG_ M2I_Byrack_HVS_IMM27_15 : 8|16@1+ (0.1,0) [0|6553.5] "v"  IMM
 SG_ M2I_Byrack_Enable_IMM27_15 : 24|2@1+ (1,0) [0|3] ""  IMM
 SG_ M2I_Byrack_ReVeEnable_IMM27_15 : 26|2@1+ (1,0) [0|3] ""  IMM
 SG_ Reserved_15 : 28|4@1+ (1,0) [0|15] ""  IMM
 SG_ M2I_Byrack_IsPostTm_IMM27_15 : 32|8@1+ (0.01,0) [0|2.55] "s"  IMM
 SG_ M2I_Byrack_SysABStTm_IMM27_15 : 40|16@1+ (0.01,0) [0|655.35] "s"  IMM
 SG_ Reserved_15 : 56|8@1+ (1,0) [0|255] ""  IMM

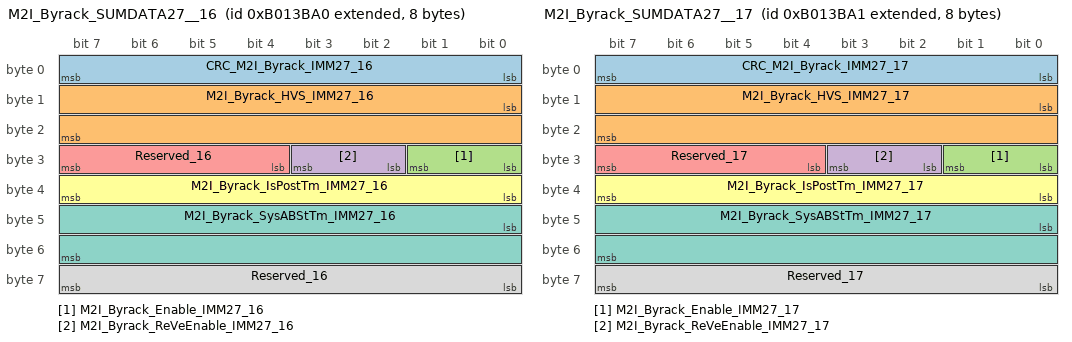
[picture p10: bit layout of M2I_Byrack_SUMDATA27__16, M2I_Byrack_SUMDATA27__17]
BO_ 2332113824 M2I_Byrack_SUMDATA27__16: 8 MBMU
 SG_ CRC_M2I_Byrack_IMM27_16 : 0|8@1+ (1,0) [0|255] ""  IMM
 SG_ M2I_Byrack_HVS_IMM27_16 : 8|16@1+ (0.1,0) [0|6553.5] "v"  IMM
 SG_ M2I_Byrack_Enable_IMM27_16 : 24|2@1+ (1,0) [0|3] ""  IMM
 SG_ M2I_Byrack_ReVeEnable_IMM27_16 : 26|2@1+ (1,0) [0|3] ""  IMM
 SG_ Reserved_16 : 28|4@1+ (1,0) [0|15] ""  IMM
 SG_ M2I_Byrack_IsPostTm_IMM27_16 : 32|8@1+ (0.01,0) [0|2.55] "s"  IMM
 SG_ M2I_Byrack_SysABStTm_IMM27_16 : 40|16@1+ (0.01,0) [0|655.35] "s"  IMM
 SG_ Reserved_16 : 56|8@1+ (1,0) [0|255] ""  IMM

BO_ 2332113825 M2I_Byrack_SUMDATA27__17: 8 MBMU
 SG_ CRC_M2I_Byrack_IMM27_17 : 0|8@1+ (1,0) [0|255] ""  IMM
 SG_ M2I_Byrack_HVS_IMM27_17 : 8|16@1+ (0.1,0) [0|6553.5] "v"  IMM
 SG_ M2I_Byrack_Enable_IMM27_17 : 24|2@1+ (1,0) [0|3] ""  IMM
 SG_ M2I_Byrack_ReVeEnable_IMM27_17 : 26|2@1+ (1,0) [0|3] ""  IMM
 SG_ Reserved_17 : 28|4@1+ (1,0) [0|15] ""  IMM
 SG_ M2I_Byrack_IsPostTm_IMM27_17 : 32|8@1+ (0.01,0) [0|2.55] "s"  IMM
 SG_ M2I_Byrack_SysABStTm_IMM27_17 : 40|16@1+ (0.01,0) [0|655.35] "s"  IMM
 SG_ Reserved_17 : 56|8@1+ (1,0) [0|255] ""  IMM

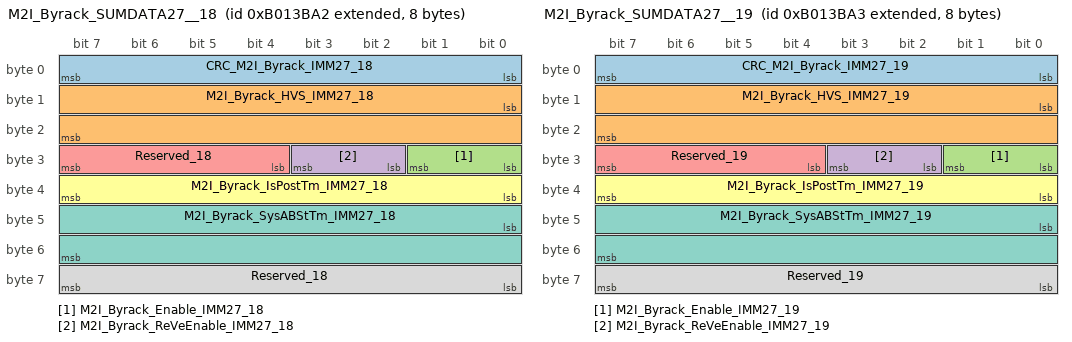
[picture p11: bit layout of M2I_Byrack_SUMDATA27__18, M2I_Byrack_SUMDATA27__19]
BO_ 2332113826 M2I_Byrack_SUMDATA27__18: 8 MBMU
 SG_ CRC_M2I_Byrack_IMM27_18 : 0|8@1+ (1,0) [0|255] ""  IMM
 SG_ M2I_Byrack_HVS_IMM27_18 : 8|16@1+ (0.1,0) [0|6553.5] "v"  IMM
 SG_ M2I_Byrack_Enable_IMM27_18 : 24|2@1+ (1,0) [0|3] ""  IMM
 SG_ M2I_Byrack_ReVeEnable_IMM27_18 : 26|2@1+ (1,0) [0|3] ""  IMM
 SG_ Reserved_18 : 28|4@1+ (1,0) [0|15] ""  IMM
 SG_ M2I_Byrack_IsPostTm_IMM27_18 : 32|8@1+ (0.01,0) [0|2.55] "s"  IMM
 SG_ M2I_Byrack_SysABStTm_IMM27_18 : 40|16@1+ (0.01,0) [0|655.35] "s"  IMM
 SG_ Reserved_18 : 56|8@1+ (1,0) [0|255] ""  IMM

BO_ 2332113827 M2I_Byrack_SUMDATA27__19: 8 MBMU
 SG_ CRC_M2I_Byrack_IMM27_19 : 0|8@1+ (1,0) [0|255] ""  IMM
 SG_ M2I_Byrack_HVS_IMM27_19 : 8|16@1+ (0.1,0) [0|6553.5] "v"  IMM
 SG_ M2I_Byrack_Enable_IMM27_19 : 24|2@1+ (1,0) [0|3] ""  IMM
 SG_ M2I_Byrack_ReVeEnable_IMM27_19 : 26|2@1+ (1,0) [0|3] ""  IMM
 SG_ Reserved_19 : 28|4@1+ (1,0) [0|15] ""  IMM
 SG_ M2I_Byrack_IsPostTm_IMM27_19 : 32|8@1+ (0.01,0) [0|2.55] "s"  IMM
 SG_ M2I_Byrack_SysABStTm_IMM27_19 : 40|16@1+ (0.01,0) [0|655.35] "s"  IMM
 SG_ Reserved_19 : 56|8@1+ (1,0) [0|255] ""  IMM

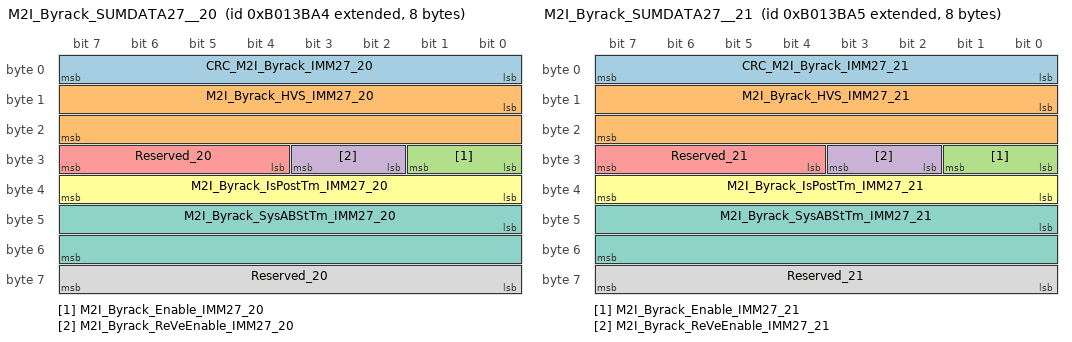
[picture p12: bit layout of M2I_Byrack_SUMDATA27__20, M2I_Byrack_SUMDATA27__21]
BO_ 2332113828 M2I_Byrack_SUMDATA27__20: 8 MBMU
 SG_ CRC_M2I_Byrack_IMM27_20 : 0|8@1+ (1,0) [0|255] ""  IMM
 SG_ M2I_Byrack_HVS_IMM27_20 : 8|16@1+ (0.1,0) [0|6553.5] "v"  IMM
 SG_ M2I_Byrack_Enable_IMM27_20 : 24|2@1+ (1,0) [0|3] ""  IMM
 SG_ M2I_Byrack_ReVeEnable_IMM27_20 : 26|2@1+ (1,0) [0|3] ""  IMM
 SG_ Reserved_20 : 28|4@1+ (1,0) [0|15] ""  IMM
 SG_ M2I_Byrack_IsPostTm_IMM27_20 : 32|8@1+ (0.01,0) [0|2.55] "s"  IMM
 SG_ M2I_Byrack_SysABStTm_IMM27_20 : 40|16@1+ (0.01,0) [0|655.35] "s"  IMM
 SG_ Reserved_20 : 56|8@1+ (1,0) [0|255] ""  IMM

BO_ 2332113829 M2I_Byrack_SUMDATA27__21: 8 MBMU
 SG_ CRC_M2I_Byrack_IMM27_21 : 0|8@1+ (1,0) [0|255] ""  IMM
 SG_ M2I_Byrack_HVS_IMM27_21 : 8|16@1+ (0.1,0) [0|6553.5] "v"  IMM
 SG_ M2I_Byrack_Enable_IMM27_21 : 24|2@1+ (1,0) [0|3] ""  IMM
 SG_ M2I_Byrack_ReVeEnable_IMM27_21 : 26|2@1+ (1,0) [0|3] ""  IMM
 SG_ Reserved_21 : 28|4@1+ (1,0) [0|15] ""  IMM
 SG_ M2I_Byrack_IsPostTm_IMM27_21 : 32|8@1+ (0.01,0) [0|2.55] "s"  IMM
 SG_ M2I_Byrack_SysABStTm_IMM27_21 : 40|16@1+ (0.01,0) [0|655.35] "s"  IMM
 SG_ Reserved_21 : 56|8@1+ (1,0) [0|255] ""  IMM

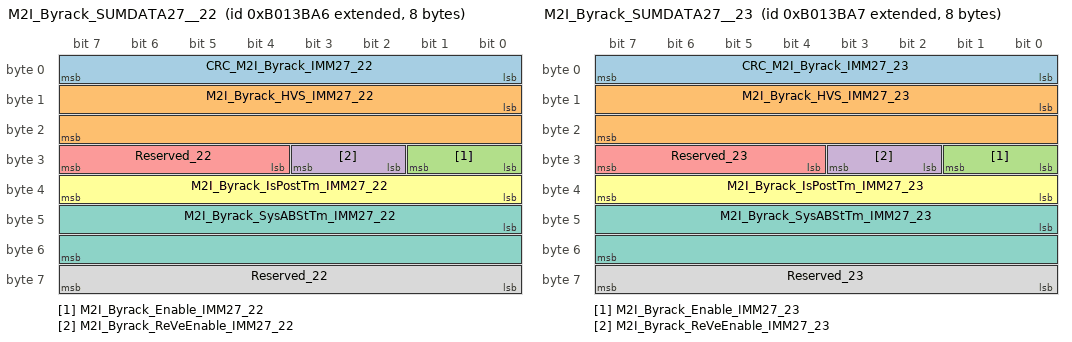
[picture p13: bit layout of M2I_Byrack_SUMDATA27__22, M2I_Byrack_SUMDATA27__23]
BO_ 2332113830 M2I_Byrack_SUMDATA27__22: 8 MBMU
 SG_ CRC_M2I_Byrack_IMM27_22 : 0|8@1+ (1,0) [0|255] ""  IMM
 SG_ M2I_Byrack_HVS_IMM27_22 : 8|16@1+ (0.1,0) [0|6553.5] "v"  IMM
 SG_ M2I_Byrack_Enable_IMM27_22 : 24|2@1+ (1,0) [0|3] ""  IMM
 SG_ M2I_Byrack_ReVeEnable_IMM27_22 : 26|2@1+ (1,0) [0|3] ""  IMM
 SG_ Reserved_22 : 28|4@1+ (1,0) [0|15] ""  IMM
 SG_ M2I_Byrack_IsPostTm_IMM27_22 : 32|8@1+ (0.01,0) [0|2.55] "s"  IMM
 SG_ M2I_Byrack_SysABStTm_IMM27_22 : 40|16@1+ (0.01,0) [0|655.35] "s"  IMM
 SG_ Reserved_22 : 56|8@1+ (1,0) [0|255] ""  IMM

BO_ 2332113831 M2I_Byrack_SUMDATA27__23: 8 MBMU
 SG_ CRC_M2I_Byrack_IMM27_23 : 0|8@1+ (1,0) [0|255] ""  IMM
 SG_ M2I_Byrack_HVS_IMM27_23 : 8|16@1+ (0.1,0) [0|6553.5] "v"  IMM
 SG_ M2I_Byrack_Enable_IMM27_23 : 24|2@1+ (1,0) [0|3] ""  IMM
 SG_ M2I_Byrack_ReVeEnable_IMM27_23 : 26|2@1+ (1,0) [0|3] ""  IMM
 SG_ Reserved_23 : 28|4@1+ (1,0) [0|15] ""  IMM
 SG_ M2I_Byrack_IsPostTm_IMM27_23 : 32|8@1+ (0.01,0) [0|2.55] "s"  IMM
 SG_ M2I_Byrack_SysABStTm_IMM27_23 : 40|16@1+ (0.01,0) [0|655.35] "s"  IMM
 SG_ Reserved_23 : 56|8@1+ (1,0) [0|255] ""  IMM

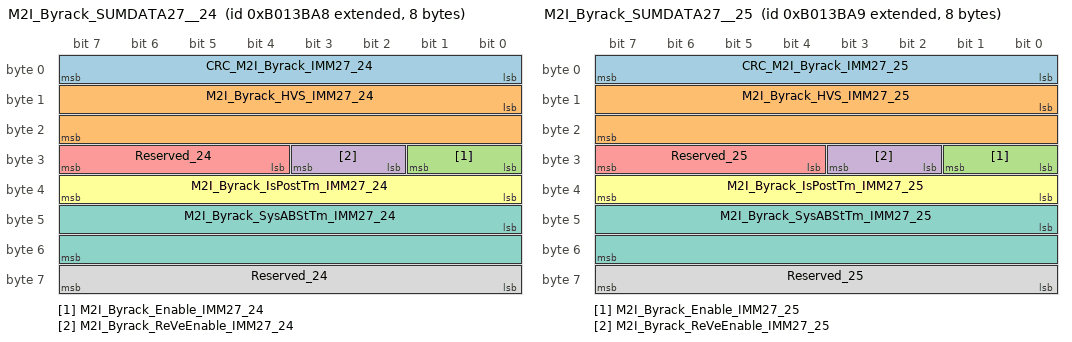
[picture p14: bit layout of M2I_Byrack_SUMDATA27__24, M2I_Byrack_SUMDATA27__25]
BO_ 2332113832 M2I_Byrack_SUMDATA27__24: 8 MBMU
 SG_ CRC_M2I_Byrack_IMM27_24 : 0|8@1+ (1,0) [0|255] ""  IMM
 SG_ M2I_Byrack_HVS_IMM27_24 : 8|16@1+ (0.1,0) [0|6553.5] "v"  IMM
 SG_ M2I_Byrack_Enable_IMM27_24 : 24|2@1+ (1,0) [0|3] ""  IMM
 SG_ M2I_Byrack_ReVeEnable_IMM27_24 : 26|2@1+ (1,0) [0|3] ""  IMM
 SG_ Reserved_24 : 28|4@1+ (1,0) [0|15] ""  IMM
 SG_ M2I_Byrack_IsPostTm_IMM27_24 : 32|8@1+ (0.01,0) [0|2.55] "s"  IMM
 SG_ M2I_Byrack_SysABStTm_IMM27_24 : 40|16@1+ (0.01,0) [0|655.35] "s"  IMM
 SG_ Reserved_24 : 56|8@1+ (1,0) [0|255] ""  IMM

BO_ 2332113833 M2I_Byrack_SUMDATA27__25: 8 MBMU
 SG_ CRC_M2I_Byrack_IMM27_25 : 0|8@1+ (1,0) [0|255] ""  IMM
 SG_ M2I_Byrack_HVS_IMM27_25 : 8|16@1+ (0.1,0) [0|6553.5] "v"  IMM
 SG_ M2I_Byrack_Enable_IMM27_25 : 24|2@1+ (1,0) [0|3] ""  IMM
 SG_ M2I_Byrack_ReVeEnable_IMM27_25 : 26|2@1+ (1,0) [0|3] ""  IMM
 SG_ Reserved_25 : 28|4@1+ (1,0) [0|15] ""  IMM
 SG_ M2I_Byrack_IsPostTm_IMM27_25 : 32|8@1+ (0.01,0) [0|2.55] "s"  IMM
 SG_ M2I_Byrack_SysABStTm_IMM27_25 : 40|16@1+ (0.01,0) [0|655.35] "s"  IMM
 SG_ Reserved_25 : 56|8@1+ (1,0) [0|255] ""  IMM

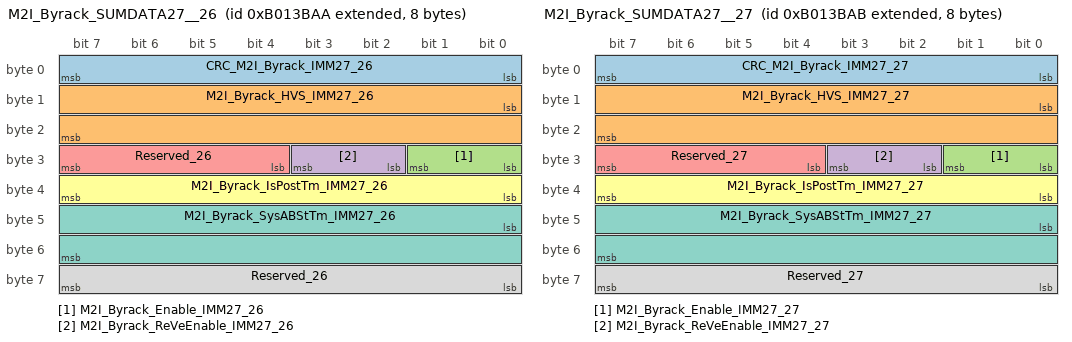
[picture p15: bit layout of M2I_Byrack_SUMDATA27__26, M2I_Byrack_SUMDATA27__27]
BO_ 2332113834 M2I_Byrack_SUMDATA27__26: 8 MBMU
 SG_ CRC_M2I_Byrack_IMM27_26 : 0|8@1+ (1,0) [0|255] ""  IMM
 SG_ M2I_Byrack_HVS_IMM27_26 : 8|16@1+ (0.1,0) [0|6553.5] "v"  IMM
 SG_ M2I_Byrack_Enable_IMM27_26 : 24|2@1+ (1,0) [0|3] ""  IMM
 SG_ M2I_Byrack_ReVeEnable_IMM27_26 : 26|2@1+ (1,0) [0|3] ""  IMM
 SG_ Reserved_26 : 28|4@1+ (1,0) [0|15] ""  IMM
 SG_ M2I_Byrack_IsPostTm_IMM27_26 : 32|8@1+ (0.01,0) [0|2.55] "s"  IMM
 SG_ M2I_Byrack_SysABStTm_IMM27_26 : 40|16@1+ (0.01,0) [0|655.35] "s"  IMM
 SG_ Reserved_26 : 56|8@1+ (1,0) [0|255] ""  IMM

BO_ 2332113835 M2I_Byrack_SUMDATA27__27: 8 MBMU
 SG_ CRC_M2I_Byrack_IMM27_27 : 0|8@1+ (1,0) [0|255] ""  IMM
 SG_ M2I_Byrack_HVS_IMM27_27 : 8|16@1+ (0.1,0) [0|6553.5] "v"  IMM
 SG_ M2I_Byrack_Enable_IMM27_27 : 24|2@1+ (1,0) [0|3] ""  IMM
 SG_ M2I_Byrack_ReVeEnable_IMM27_27 : 26|2@1+ (1,0) [0|3] ""  IMM
 SG_ Reserved_27 : 28|4@1+ (1,0) [0|15] ""  IMM
 SG_ M2I_Byrack_IsPostTm_IMM27_27 : 32|8@1+ (0.01,0) [0|2.55] "s"  IMM
 SG_ M2I_Byrack_SysABStTm_IMM27_27 : 40|16@1+ (0.01,0) [0|655.35] "s"  IMM
 SG_ Reserved_27 : 56|8@1+ (1,0) [0|255] ""  IMM

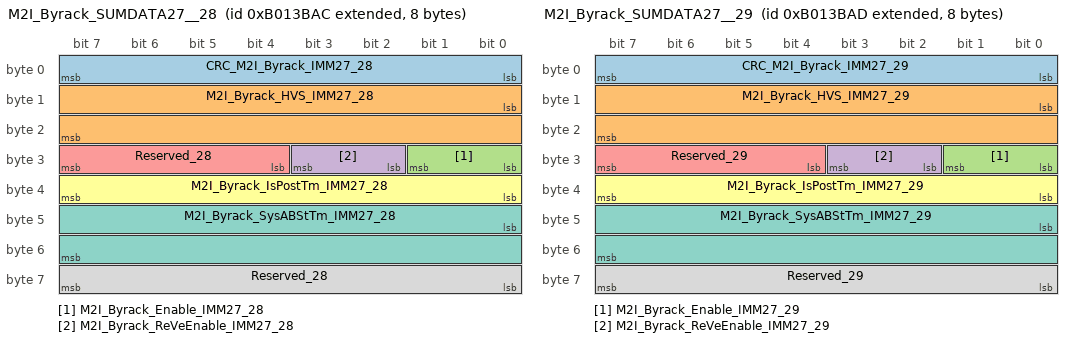
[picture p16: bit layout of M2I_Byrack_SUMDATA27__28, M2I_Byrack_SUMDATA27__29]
BO_ 2332113836 M2I_Byrack_SUMDATA27__28: 8 MBMU
 SG_ CRC_M2I_Byrack_IMM27_28 : 0|8@1+ (1,0) [0|255] ""  IMM
 SG_ M2I_Byrack_HVS_IMM27_28 : 8|16@1+ (0.1,0) [0|6553.5] "v"  IMM
 SG_ M2I_Byrack_Enable_IMM27_28 : 24|2@1+ (1,0) [0|3] ""  IMM
 SG_ M2I_Byrack_ReVeEnable_IMM27_28 : 26|2@1+ (1,0) [0|3] ""  IMM
 SG_ Reserved_28 : 28|4@1+ (1,0) [0|15] ""  IMM
 SG_ M2I_Byrack_IsPostTm_IMM27_28 : 32|8@1+ (0.01,0) [0|2.55] "s"  IMM
 SG_ M2I_Byrack_SysABStTm_IMM27_28 : 40|16@1+ (0.01,0) [0|655.35] "s"  IMM
 SG_ Reserved_28 : 56|8@1+ (1,0) [0|255] ""  IMM

BO_ 2332113837 M2I_Byrack_SUMDATA27__29: 8 MBMU
 SG_ CRC_M2I_Byrack_IMM27_29 : 0|8@1+ (1,0) [0|255] ""  IMM
 SG_ M2I_Byrack_HVS_IMM27_29 : 8|16@1+ (0.1,0) [0|6553.5] "v"  IMM
 SG_ M2I_Byrack_Enable_IMM27_29 : 24|2@1+ (1,0) [0|3] ""  IMM
 SG_ M2I_Byrack_ReVeEnable_IMM27_29 : 26|2@1+ (1,0) [0|3] ""  IMM
 SG_ Reserved_29 : 28|4@1+ (1,0) [0|15] ""  IMM
 SG_ M2I_Byrack_IsPostTm_IMM27_29 : 32|8@1+ (0.01,0) [0|2.55] "s"  IMM
 SG_ M2I_Byrack_SysABStTm_IMM27_29 : 40|16@1+ (0.01,0) [0|655.35] "s"  IMM
 SG_ Reserved_29 : 56|8@1+ (1,0) [0|255] ""  IMM

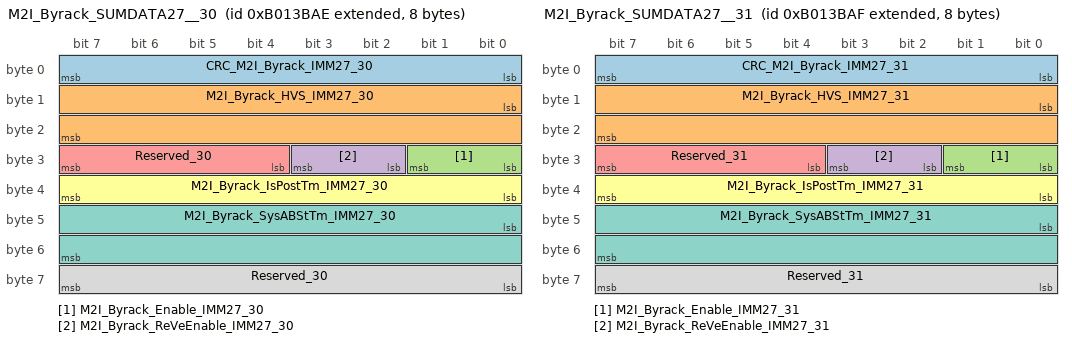
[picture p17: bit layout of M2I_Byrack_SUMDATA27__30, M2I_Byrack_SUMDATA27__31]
BO_ 2332113838 M2I_Byrack_SUMDATA27__30: 8 MBMU
 SG_ CRC_M2I_Byrack_IMM27_30 : 0|8@1+ (1,0) [0|255] ""  IMM
 SG_ M2I_Byrack_HVS_IMM27_30 : 8|16@1+ (0.1,0) [0|6553.5] "v"  IMM
 SG_ M2I_Byrack_Enable_IMM27_30 : 24|2@1+ (1,0) [0|3] ""  IMM
 SG_ M2I_Byrack_ReVeEnable_IMM27_30 : 26|2@1+ (1,0) [0|3] ""  IMM
 SG_ Reserved_30 : 28|4@1+ (1,0) [0|15] ""  IMM
 SG_ M2I_Byrack_IsPostTm_IMM27_30 : 32|8@1+ (0.01,0) [0|2.55] "s"  IMM
 SG_ M2I_Byrack_SysABStTm_IMM27_30 : 40|16@1+ (0.01,0) [0|655.35] "s"  IMM
 SG_ Reserved_30 : 56|8@1+ (1,0) [0|255] ""  IMM

BO_ 2332113839 M2I_Byrack_SUMDATA27__31: 8 MBMU
 SG_ CRC_M2I_Byrack_IMM27_31 : 0|8@1+ (1,0) [0|255] ""  IMM
 SG_ M2I_Byrack_HVS_IMM27_31 : 8|16@1+ (0.1,0) [0|6553.5] "v"  IMM
 SG_ M2I_Byrack_Enable_IMM27_31 : 24|2@1+ (1,0) [0|3] ""  IMM
 SG_ M2I_Byrack_ReVeEnable_IMM27_31 : 26|2@1+ (1,0) [0|3] ""  IMM
 SG_ Reserved_31 : 28|4@1+ (1,0) [0|15] ""  IMM
 SG_ M2I_Byrack_IsPostTm_IMM27_31 : 32|8@1+ (0.01,0) [0|2.55] "s"  IMM
 SG_ M2I_Byrack_SysABStTm_IMM27_31 : 40|16@1+ (0.01,0) [0|655.35] "s"  IMM
 SG_ Reserved_31 : 56|8@1+ (1,0) [0|255] ""  IMM

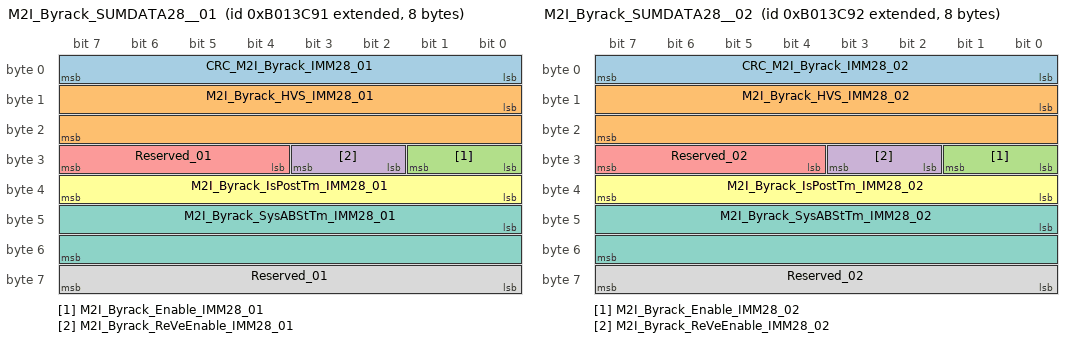
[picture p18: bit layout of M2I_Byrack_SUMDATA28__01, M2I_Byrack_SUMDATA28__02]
BO_ 2332114065 M2I_Byrack_SUMDATA28__01: 8 MBMU
 SG_ CRC_M2I_Byrack_IMM28_01 : 0|8@1+ (1,0) [0|255] ""  IMM
 SG_ M2I_Byrack_HVS_IMM28_01 : 8|16@1+ (0.1,0) [0|6553.5] "v"  IMM
 SG_ M2I_Byrack_Enable_IMM28_01 : 24|2@1+ (1,0) [0|3] ""  IMM
 SG_ M2I_Byrack_ReVeEnable_IMM28_01 : 26|2@1+ (1,0) [0|3] ""  IMM
 SG_ Reserved_01 : 28|4@1+ (1,0) [0|15] ""  IMM
 SG_ M2I_Byrack_IsPostTm_IMM28_01 : 32|8@1+ (0.01,0) [0|2.55] "s"  IMM
 SG_ M2I_Byrack_SysABStTm_IMM28_01 : 40|16@1+ (0.01,0) [0|655.35] "s"  IMM
 SG_ Reserved_01 : 56|8@1+ (1,0) [0|255] ""  IMM

BO_ 2332114066 M2I_Byrack_SUMDATA28__02: 8 MBMU
 SG_ CRC_M2I_Byrack_IMM28_02 : 0|8@1+ (1,0) [0|255] ""  IMM
 SG_ M2I_Byrack_HVS_IMM28_02 : 8|16@1+ (0.1,0) [0|6553.5] "v"  IMM
 SG_ M2I_Byrack_Enable_IMM28_02 : 24|2@1+ (1,0) [0|3] ""  IMM
 SG_ M2I_Byrack_ReVeEnable_IMM28_02 : 26|2@1+ (1,0) [0|3] ""  IMM
 SG_ Reserved_02 : 28|4@1+ (1,0) [0|15] ""  IMM
 SG_ M2I_Byrack_IsPostTm_IMM28_02 : 32|8@1+ (0.01,0) [0|2.55] "s"  IMM
 SG_ M2I_Byrack_SysABStTm_IMM28_02 : 40|16@1+ (0.01,0) [0|655.35] "s"  IMM
 SG_ Reserved_02 : 56|8@1+ (1,0) [0|255] ""  IMM

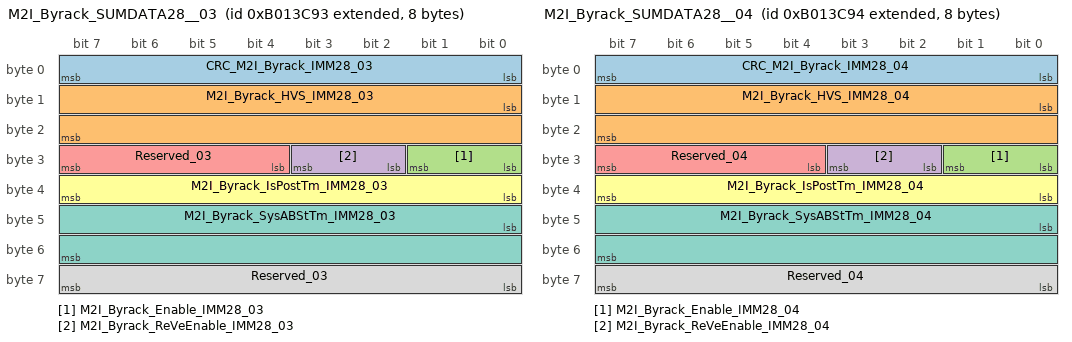
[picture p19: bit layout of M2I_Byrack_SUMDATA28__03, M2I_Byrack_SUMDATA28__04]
BO_ 2332114067 M2I_Byrack_SUMDATA28__03: 8 MBMU
 SG_ CRC_M2I_Byrack_IMM28_03 : 0|8@1+ (1,0) [0|255] ""  IMM
 SG_ M2I_Byrack_HVS_IMM28_03 : 8|16@1+ (0.1,0) [0|6553.5] "v"  IMM
 SG_ M2I_Byrack_Enable_IMM28_03 : 24|2@1+ (1,0) [0|3] ""  IMM
 SG_ M2I_Byrack_ReVeEnable_IMM28_03 : 26|2@1+ (1,0) [0|3] ""  IMM
 SG_ Reserved_03 : 28|4@1+ (1,0) [0|15] ""  IMM
 SG_ M2I_Byrack_IsPostTm_IMM28_03 : 32|8@1+ (0.01,0) [0|2.55] "s"  IMM
 SG_ M2I_Byrack_SysABStTm_IMM28_03 : 40|16@1+ (0.01,0) [0|655.35] "s"  IMM
 SG_ Reserved_03 : 56|8@1+ (1,0) [0|255] ""  IMM

BO_ 2332114068 M2I_Byrack_SUMDATA28__04: 8 MBMU
 SG_ CRC_M2I_Byrack_IMM28_04 : 0|8@1+ (1,0) [0|255] ""  IMM
 SG_ M2I_Byrack_HVS_IMM28_04 : 8|16@1+ (0.1,0) [0|6553.5] "v"  IMM
 SG_ M2I_Byrack_Enable_IMM28_04 : 24|2@1+ (1,0) [0|3] ""  IMM
 SG_ M2I_Byrack_ReVeEnable_IMM28_04 : 26|2@1+ (1,0) [0|3] ""  IMM
 SG_ Reserved_04 : 28|4@1+ (1,0) [0|15] ""  IMM
 SG_ M2I_Byrack_IsPostTm_IMM28_04 : 32|8@1+ (0.01,0) [0|2.55] "s"  IMM
 SG_ M2I_Byrack_SysABStTm_IMM28_04 : 40|16@1+ (0.01,0) [0|655.35] "s"  IMM
 SG_ Reserved_04 : 56|8@1+ (1,0) [0|255] ""  IMM

BO_ 2332114069 M2I_Byrack_SUMDATA28__05: 8 MBMU
 SG_ CRC_M2I_Byrack_IMM28_05 : 0|8@1+ (1,0) [0|255] ""  IMM
 SG_ M2I_Byrack_HVS_IMM28_05 : 8|16@1+ (0.1,0) [0|6553.5] "v"  IMM
 SG_ M2I_Byrack_Enable_IMM28_05 : 24|2@1+ (1,0) [0|3] ""  IMM
 SG_ M2I_Byrack_ReVeEnable_IMM28_05 : 26|2@1+ (1,0) [0|3] ""  IMM
 SG_ Reserved_05 : 28|4@1+ (1,0) [0|15] ""  IMM
 SG_ M2I_Byrack_IsPostTm_IMM28_05 : 32|8@1+ (0.01,0) [0|2.55] "s"  IMM
 SG_ M2I_Byrack_SysABStTm_IMM28_05 : 40|16@1+ (0.01,0) [0|655.35] "s"  IMM
 SG_ Reserved_05 : 56|8@1+ (1,0) [0|255] ""  IMM

BO_ 2332114070 M2I_Byrack_SUMDATA28__06: 8 MBMU
 SG_ CRC_M2I_Byrack_IMM28_06 : 0|8@1+ (1,0) [0|255] ""  IMM
 SG_ M2I_Byrack_HVS_IMM28_06 : 8|16@1+ (0.1,0) [0|6553.5] "v"  IMM
 SG_ M2I_Byrack_Enable_IMM28_06 : 24|2@1+ (1,0) [0|3] ""  IMM
 SG_ M2I_Byrack_ReVeEnable_IMM28_06 : 26|2@1+ (1,0) [0|3] ""  IMM
 SG_ Reserved_06 : 28|4@1+ (1,0) [0|15] ""  IMM
 SG_ M2I_Byrack_IsPostTm_IMM28_06 : 32|8@1+ (0.01,0) [0|2.55] "s"  IMM
 SG_ M2I_Byrack_SysABStTm_IMM28_06 : 40|16@1+ (0.01,0) [0|655.35] "s"  IMM
 SG_ Reserved_06 : 56|8@1+ (1,0) [0|255] ""  IMM

BO_ 2332114071 M2I_Byrack_SUMDATA28__07: 8 MBMU
 SG_ CRC_M2I_Byrack_IMM28_07 : 0|8@1+ (1,0) [0|255] ""  IMM
 SG_ M2I_Byrack_HVS_IMM28_07 : 8|16@1+ (0.1,0) [0|6553.5] "v"  IMM
 SG_ M2I_Byrack_Enable_IMM28_07 : 24|2@1+ (1,0) [0|3] ""  IMM
 SG_ M2I_Byrack_ReVeEnable_IMM28_07 : 26|2@1+ (1,0) [0|3] ""  IMM
 SG_ Reserved_07 : 28|4@1+ (1,0) [0|15] ""  IMM
 SG_ M2I_Byrack_IsPostTm_IMM28_07 : 32|8@1+ (0.01,0) [0|2.55] "s"  IMM
 SG_ M2I_Byrack_SysABStTm_IMM28_07 : 40|16@1+ (0.01,0) [0|655.35] "s"  IMM
 SG_ Reserved_07 : 56|8@1+ (1,0) [0|255] ""  IMM

BO_ 2332114072 M2I_Byrack_SUMDATA28__08: 8 MBMU
 SG_ CRC_M2I_Byrack_IMM28_08 : 0|8@1+ (1,0) [0|255] ""  IMM
 SG_ M2I_Byrack_HVS_IMM28_08 : 8|16@1+ (0.1,0) [0|6553.5] "v"  IMM
 SG_ M2I_Byrack_Enable_IMM28_08 : 24|2@1+ (1,0) [0|3] ""  IMM
 SG_ M2I_Byrack_ReVeEnable_IMM28_08 : 26|2@1+ (1,0) [0|3] ""  IMM
 SG_ Reserved_08 : 28|4@1+ (1,0) [0|15] ""  IMM
 SG_ M2I_Byrack_IsPostTm_IMM28_08 : 32|8@1+ (0.01,0) [0|2.55] "s"  IMM
 SG_ M2I_Byrack_SysABStTm_IMM28_08 : 40|16@1+ (0.01,0) [0|655.35] "s"  IMM
 SG_ Reserved_08 : 56|8@1+ (1,0) [0|255] ""  IMM

BO_ 2332114073 M2I_Byrack_SUMDATA28__09: 8 MBMU
 SG_ CRC_M2I_Byrack_IMM28_09 : 0|8@1+ (1,0) [0|255] ""  IMM
 SG_ M2I_Byrack_HVS_IMM28_09 : 8|16@1+ (0.1,0) [0|6553.5] "v"  IMM
 SG_ M2I_Byrack_Enable_IMM28_09 : 24|2@1+ (1,0) [0|3] ""  IMM
 SG_ M2I_Byrack_ReVeEnable_IMM28_09 : 26|2@1+ (1,0) [0|3] ""  IMM
 SG_ Reserved_09 : 28|4@1+ (1,0) [0|15] ""  IMM
 SG_ M2I_Byrack_IsPostTm_IMM28_09 : 32|8@1+ (0.01,0) [0|2.55] "s"  IMM
 SG_ M2I_Byrack_SysABStTm_IMM28_09 : 40|16@1+ (0.01,0) [0|655.35] "s"  IMM
 SG_ Reserved_09 : 56|8@1+ (1,0) [0|255] ""  IMM

BO_ 2332114074 M2I_Byrack_SUMDATA28__10: 8 MBMU
 SG_ CRC_M2I_Byrack_IMM28_10 : 0|8@1+ (1,0) [0|255] ""  IMM
 SG_ M2I_Byrack_HVS_IMM28_10 : 8|16@1+ (0.1,0) [0|6553.5] "v"  IMM
 SG_ M2I_Byrack_Enable_IMM28_10 : 24|2@1+ (1,0) [0|3] ""  IMM
 SG_ M2I_Byrack_ReVeEnable_IMM28_10 : 26|2@1+ (1,0) [0|3] ""  IMM
 SG_ Reserved_10 : 28|4@1+ (1,0) [0|15] ""  IMM
 SG_ M2I_Byrack_IsPostTm_IMM28_10 : 32|8@1+ (0.01,0) [0|2.55] "s"  IMM
 SG_ M2I_Byrack_SysABStTm_IMM28_10 : 40|16@1+ (0.01,0) [0|655.35] "s"  IMM
 SG_ Reserved_10 : 56|8@1+ (1,0) [0|255] ""  IMM

BO_ 2332114075 M2I_Byrack_SUMDATA28__11: 8 MBMU
 SG_ CRC_M2I_Byrack_IMM28_11 : 0|8@1+ (1,0) [0|255] ""  IMM
 SG_ M2I_Byrack_HVS_IMM28_11 : 8|16@1+ (0.1,0) [0|6553.5] "v"  IMM
 SG_ M2I_Byrack_Enable_IMM28_11 : 24|2@1+ (1,0) [0|3] ""  IMM
 SG_ M2I_Byrack_ReVeEnable_IMM28_11 : 26|2@1+ (1,0) [0|3] ""  IMM
 SG_ Reserved_11 : 28|4@1+ (1,0) [0|15] ""  IMM
 SG_ M2I_Byrack_IsPostTm_IMM28_11 : 32|8@1+ (0.01,0) [0|2.55] "s"  IMM
 SG_ M2I_Byrack_SysABStTm_IMM28_11 : 40|16@1+ (0.01,0) [0|655.35] "s"  IMM
 SG_ Reserved_11 : 56|8@1+ (1,0) [0|255] ""  IMM

BO_ 2332114076 M2I_Byrack_SUMDATA28__12: 8 MBMU
 SG_ CRC_M2I_Byrack_IMM28_12 : 0|8@1+ (1,0) [0|255] ""  IMM
 SG_ M2I_Byrack_HVS_IMM28_12 : 8|16@1+ (0.1,0) [0|6553.5] "v"  IMM
 SG_ M2I_Byrack_Enable_IMM28_12 : 24|2@1+ (1,0) [0|3] ""  IMM
 SG_ M2I_Byrack_ReVeEnable_IMM28_12 : 26|2@1+ (1,0) [0|3] ""  IMM
 SG_ Reserved_12 : 28|4@1+ (1,0) [0|15] ""  IMM
 SG_ M2I_Byrack_IsPostTm_IMM28_12 : 32|8@1+ (0.01,0) [0|2.55] "s"  IMM
 SG_ M2I_Byrack_SysABStTm_IMM28_12 : 40|16@1+ (0.01,0) [0|655.35] "s"  IMM
 SG_ Reserved_12 : 56|8@1+ (1,0) [0|255] ""  IMM

BO_ 2332114077 M2I_Byrack_SUMDATA28__13: 8 MBMU
 SG_ CRC_M2I_Byrack_IMM28_13 : 0|8@1+ (1,0) [0|255] ""  IMM
 SG_ M2I_Byrack_HVS_IMM28_13 : 8|16@1+ (0.1,0) [0|6553.5] "v"  IMM
 SG_ M2I_Byrack_Enable_IMM28_13 : 24|2@1+ (1,0) [0|3] ""  IMM
 SG_ M2I_Byrack_ReVeEnable_IMM28_13 : 26|2@1+ (1,0) [0|3] ""  IMM
 SG_ Reserved_13 : 28|4@1+ (1,0) [0|15] ""  IMM
 SG_ M2I_Byrack_IsPostTm_IMM28_13 : 32|8@1+ (0.01,0) [0|2.55] "s"  IMM
 SG_ M2I_Byrack_SysABStTm_IMM28_13 : 40|16@1+ (0.01,0) [0|655.35] "s"  IMM
 SG_ Reserved_13 : 56|8@1+ (1,0) [0|255] ""  IMM

BO_ 2332114078 M2I_Byrack_SUMDATA28__14: 8 MBMU
 SG_ CRC_M2I_Byrack_IMM28_14 : 0|8@1+ (1,0) [0|255] ""  IMM
 SG_ M2I_Byrack_HVS_IMM28_14 : 8|16@1+ (0.1,0) [0|6553.5] "v"  IMM
 SG_ M2I_Byrack_Enable_IMM28_14 : 24|2@1+ (1,0) [0|3] ""  IMM
 SG_ M2I_Byrack_ReVeEnable_IMM28_14 : 26|2@1+ (1,0) [0|3] ""  IMM
 SG_ Reserved_14 : 28|4@1+ (1,0) [0|15] ""  IMM
 SG_ M2I_Byrack_IsPostTm_IMM28_14 : 32|8@1+ (0.01,0) [0|2.55] "s"  IMM
 SG_ M2I_Byrack_SysABStTm_IMM28_14 : 40|16@1+ (0.01,0) [0|655.35] "s"  IMM
 SG_ Reserved_14 : 56|8@1+ (1,0) [0|255] ""  IMM

BO_ 2332114079 M2I_Byrack_SUMDATA28__15: 8 MBMU
 SG_ CRC_M2I_Byrack_IMM28_15 : 0|8@1+ (1,0) [0|255] ""  IMM
 SG_ M2I_Byrack_HVS_IMM28_15 : 8|16@1+ (0.1,0) [0|6553.5] "v"  IMM
 SG_ M2I_Byrack_Enable_IMM28_15 : 24|2@1+ (1,0) [0|3] ""  IMM
 SG_ M2I_Byrack_ReVeEnable_IMM28_15 : 26|2@1+ (1,0) [0|3] ""  IMM
 SG_ Reserved_15 : 28|4@1+ (1,0) [0|15] ""  IMM
 SG_ M2I_Byrack_IsPostTm_IMM28_15 : 32|8@1+ (0.01,0) [0|2.55] "s"  IMM
 SG_ M2I_Byrack_SysABStTm_IMM28_15 : 40|16@1+ (0.01,0) [0|655.35] "s"  IMM
 SG_ Reserved_15 : 56|8@1+ (1,0) [0|255] ""  IMM

BO_ 2332114080 M2I_Byrack_SUMDATA28__16: 8 MBMU
 SG_ CRC_M2I_Byrack_IMM28_16 : 0|8@1+ (1,0) [0|255] ""  IMM
 SG_ M2I_Byrack_HVS_IMM28_16 : 8|16@1+ (0.1,0) [0|6553.5] "v"  IMM
 SG_ M2I_Byrack_Enable_IMM28_16 : 24|2@1+ (1,0) [0|3] ""  IMM
 SG_ M2I_Byrack_ReVeEnable_IMM28_16 : 26|2@1+ (1,0) [0|3] ""  IMM
 SG_ Reserved_16 : 28|4@1+ (1,0) [0|15] ""  IMM
 SG_ M2I_Byrack_IsPostTm_IMM28_16 : 32|8@1+ (0.01,0) [0|2.55] "s"  IMM
 SG_ M2I_Byrack_SysABStTm_IMM28_16 : 40|16@1+ (0.01,0) [0|655.35] "s"  IMM
 SG_ Reserved_16 : 56|8@1+ (1,0) [0|255] ""  IMM

BO_ 2332114081 M2I_Byrack_SUMDATA28__17: 8 MBMU
 SG_ CRC_M2I_Byrack_IMM28_17 : 0|8@1+ (1,0) [0|255] ""  IMM
 SG_ M2I_Byrack_HVS_IMM28_17 : 8|16@1+ (0.1,0) [0|6553.5] "v"  IMM
 SG_ M2I_Byrack_Enable_IMM28_17 : 24|2@1+ (1,0) [0|3] ""  IMM
 SG_ M2I_Byrack_ReVeEnable_IMM28_17 : 26|2@1+ (1,0) [0|3] ""  IMM
 SG_ Reserved_17 : 28|4@1+ (1,0) [0|15] ""  IMM
 SG_ M2I_Byrack_IsPostTm_IMM28_17 : 32|8@1+ (0.01,0) [0|2.55] "s"  IMM
 SG_ M2I_Byrack_SysABStTm_IMM28_17 : 40|16@1+ (0.01,0) [0|655.35] "s"  IMM
 SG_ Reserved_17 : 56|8@1+ (1,0) [0|255] ""  IMM

BO_ 2332114082 M2I_Byrack_SUMDATA28__18: 8 MBMU
 SG_ CRC_M2I_Byrack_IMM28_18 : 0|8@1+ (1,0) [0|255] ""  IMM
 SG_ M2I_Byrack_HVS_IMM28_18 : 8|16@1+ (0.1,0) [0|6553.5] "v"  IMM
 SG_ M2I_Byrack_Enable_IMM28_18 : 24|2@1+ (1,0) [0|3] ""  IMM
 SG_ M2I_Byrack_ReVeEnable_IMM28_18 : 26|2@1+ (1,0) [0|3] ""  IMM
 SG_ Reserved_18 : 28|4@1+ (1,0) [0|15] ""  IMM
 SG_ M2I_Byrack_IsPostTm_IMM28_18 : 32|8@1+ (0.01,0) [0|2.55] "s"  IMM
 SG_ M2I_Byrack_SysABStTm_IMM28_18 : 40|16@1+ (0.01,0) [0|655.35] "s"  IMM
 SG_ Reserved_18 : 56|8@1+ (1,0) [0|255] ""  IMM

BO_ 2332114083 M2I_Byrack_SUMDATA28__19: 8 MBMU
 SG_ CRC_M2I_Byrack_IMM28_19 : 0|8@1+ (1,0) [0|255] ""  IMM
 SG_ M2I_Byrack_HVS_IMM28_19 : 8|16@1+ (0.1,0) [0|6553.5] "v"  IMM
 SG_ M2I_Byrack_Enable_IMM28_19 : 24|2@1+ (1,0) [0|3] ""  IMM
 SG_ M2I_Byrack_ReVeEnable_IMM28_19 : 26|2@1+ (1,0) [0|3] ""  IMM
 SG_ Reserved_19 : 28|4@1+ (1,0) [0|15] ""  IMM
 SG_ M2I_Byrack_IsPostTm_IMM28_19 : 32|8@1+ (0.01,0) [0|2.55] "s"  IMM
 SG_ M2I_Byrack_SysABStTm_IMM28_19 : 40|16@1+ (0.01,0) [0|655.35] "s"  IMM
 SG_ Reserved_19 : 56|8@1+ (1,0) [0|255] ""  IMM

BO_ 2332114084 M2I_Byrack_SUMDATA28__20: 8 MBMU
 SG_ CRC_M2I_Byrack_IMM28_20 : 0|8@1+ (1,0) [0|255] ""  IMM
 SG_ M2I_Byrack_HVS_IMM28_20 : 8|16@1+ (0.1,0) [0|6553.5] "v"  IMM
 SG_ M2I_Byrack_Enable_IMM28_20 : 24|2@1+ (1,0) [0|3] ""  IMM
 SG_ M2I_Byrack_ReVeEnable_IMM28_20 : 26|2@1+ (1,0) [0|3] ""  IMM
 SG_ Reserved_20 : 28|4@1+ (1,0) [0|15] ""  IMM
 SG_ M2I_Byrack_IsPostTm_IMM28_20 : 32|8@1+ (0.01,0) [0|2.55] "s"  IMM
 SG_ M2I_Byrack_SysABStTm_IMM28_20 : 40|16@1+ (0.01,0) [0|655.35] "s"  IMM
 SG_ Reserved_20 : 56|8@1+ (1,0) [0|255] ""  IMM

BO_ 2332114085 M2I_Byrack_SUMDATA28__21: 8 MBMU
 SG_ CRC_M2I_Byrack_IMM28_21 : 0|8@1+ (1,0) [0|255] ""  IMM
 SG_ M2I_Byrack_HVS_IMM28_21 : 8|16@1+ (0.1,0) [0|6553.5] "v"  IMM
 SG_ M2I_Byrack_Enable_IMM28_21 : 24|2@1+ (1,0) [0|3] ""  IMM
 SG_ M2I_Byrack_ReVeEnable_IMM28_21 : 26|2@1+ (1,0) [0|3] ""  IMM
 SG_ Reserved_21 : 28|4@1+ (1,0) [0|15] ""  IMM
 SG_ M2I_Byrack_IsPostTm_IMM28_21 : 32|8@1+ (0.01,0) [0|2.55] "s"  IMM
 SG_ M2I_Byrack_SysABStTm_IMM28_21 : 40|16@1+ (0.01,0) [0|655.35] "s"  IMM
 SG_ Reserved_21 : 56|8@1+ (1,0) [0|255] ""  IMM

BO_ 2332114086 M2I_Byrack_SUMDATA28__22: 8 MBMU
 SG_ CRC_M2I_Byrack_IMM28_22 : 0|8@1+ (1,0) [0|255] ""  IMM
 SG_ M2I_Byrack_HVS_IMM28_22 : 8|16@1+ (0.1,0) [0|6553.5] "v"  IMM
 SG_ M2I_Byrack_Enable_IMM28_22 : 24|2@1+ (1,0) [0|3] ""  IMM
 SG_ M2I_Byrack_ReVeEnable_IMM28_22 : 26|2@1+ (1,0) [0|3] ""  IMM
 SG_ Reserved_22 : 28|4@1+ (1,0) [0|15] ""  IMM
 SG_ M2I_Byrack_IsPostTm_IMM28_22 : 32|8@1+ (0.01,0) [0|2.55] "s"  IMM
 SG_ M2I_Byrack_SysABStTm_IMM28_22 : 40|16@1+ (0.01,0) [0|655.35] "s"  IMM
 SG_ Reserved_22 : 56|8@1+ (1,0) [0|255] ""  IMM

BO_ 2332114087 M2I_Byrack_SUMDATA28__23: 8 MBMU
 SG_ CRC_M2I_Byrack_IMM28_23 : 0|8@1+ (1,0) [0|255] ""  IMM
 SG_ M2I_Byrack_HVS_IMM28_23 : 8|16@1+ (0.1,0) [0|6553.5] "v"  IMM
 SG_ M2I_Byrack_Enable_IMM28_23 : 24|2@1+ (1,0) [0|3] ""  IMM
 SG_ M2I_Byrack_ReVeEnable_IMM28_23 : 26|2@1+ (1,0) [0|3] ""  IMM
 SG_ Reserved_23 : 28|4@1+ (1,0) [0|15] ""  IMM
 SG_ M2I_Byrack_IsPostTm_IMM28_23 : 32|8@1+ (0.01,0) [0|2.55] "s"  IMM
 SG_ M2I_Byrack_SysABStTm_IMM28_23 : 40|16@1+ (0.01,0) [0|655.35] "s"  IMM
 SG_ Reserved_23 : 56|8@1+ (1,0) [0|255] ""  IMM

BO_ 2332114088 M2I_Byrack_SUMDATA28__24: 8 MBMU
 SG_ CRC_M2I_Byrack_IMM28_24 : 0|8@1+ (1,0) [0|255] ""  IMM
 SG_ M2I_Byrack_HVS_IMM28_24 : 8|16@1+ (0.1,0) [0|6553.5] "v"  IMM
 SG_ M2I_Byrack_Enable_IMM28_24 : 24|2@1+ (1,0) [0|3] ""  IMM
 SG_ M2I_Byrack_ReVeEnable_IMM28_24 : 26|2@1+ (1,0) [0|3] ""  IMM
 SG_ Reserved_24 : 28|4@1+ (1,0) [0|15] ""  IMM
 SG_ M2I_Byrack_IsPostTm_IMM28_24 : 32|8@1+ (0.01,0) [0|2.55] "s"  IMM
 SG_ M2I_Byrack_SysABStTm_IMM28_24 : 40|16@1+ (0.01,0) [0|655.35] "s"  IMM
 SG_ Reserved_24 : 56|8@1+ (1,0) [0|255] ""  IMM

BO_ 2332114089 M2I_Byrack_SUMDATA28__25: 8 MBMU
 SG_ CRC_M2I_Byrack_IMM28_25 : 0|8@1+ (1,0) [0|255] ""  IMM
 SG_ M2I_Byrack_HVS_IMM28_25 : 8|16@1+ (0.1,0) [0|6553.5] "v"  IMM
 SG_ M2I_Byrack_Enable_IMM28_25 : 24|2@1+ (1,0) [0|3] ""  IMM
 SG_ M2I_Byrack_ReVeEnable_IMM28_25 : 26|2@1+ (1,0) [0|3] ""  IMM
 SG_ Reserved_25 : 28|4@1+ (1,0) [0|15] ""  IMM
 SG_ M2I_Byrack_IsPostTm_IMM28_25 : 32|8@1+ (0.01,0) [0|2.55] "s"  IMM
 SG_ M2I_Byrack_SysABStTm_IMM28_25 : 40|16@1+ (0.01,0) [0|655.35] "s"  IMM
 SG_ Reserved_25 : 56|8@1+ (1,0) [0|255] ""  IMM

BO_ 2332114090 M2I_Byrack_SUMDATA28__26: 8 MBMU
 SG_ CRC_M2I_Byrack_IMM28_26 : 0|8@1+ (1,0) [0|255] ""  IMM
 SG_ M2I_Byrack_HVS_IMM28_26 : 8|16@1+ (0.1,0) [0|6553.5] "v"  IMM
 SG_ M2I_Byrack_Enable_IMM28_26 : 24|2@1+ (1,0) [0|3] ""  IMM
 SG_ M2I_Byrack_ReVeEnable_IMM28_26 : 26|2@1+ (1,0) [0|3] ""  IMM
 SG_ Reserved_26 : 28|4@1+ (1,0) [0|15] ""  IMM
 SG_ M2I_Byrack_IsPostTm_IMM28_26 : 32|8@1+ (0.01,0) [0|2.55] "s"  IMM
 SG_ M2I_Byrack_SysABStTm_IMM28_26 : 40|16@1+ (0.01,0) [0|655.35] "s"  IMM
 SG_ Reserved_26 : 56|8@1+ (1,0) [0|255] ""  IMM

BO_ 2332114091 M2I_Byrack_SUMDATA28__27: 8 MBMU
 SG_ CRC_M2I_Byrack_IMM28_27 : 0|8@1+ (1,0) [0|255] ""  IMM
 SG_ M2I_Byrack_HVS_IMM28_27 : 8|16@1+ (0.1,0) [0|6553.5] "v"  IMM
 SG_ M2I_Byrack_Enable_IMM28_27 : 24|2@1+ (1,0) [0|3] ""  IMM
 SG_ M2I_Byrack_ReVeEnable_IMM28_27 : 26|2@1+ (1,0) [0|3] ""  IMM
 SG_ Reserved_27 : 28|4@1+ (1,0) [0|15] ""  IMM
 SG_ M2I_Byrack_IsPostTm_IMM28_27 : 32|8@1+ (0.01,0) [0|2.55] "s"  IMM
 SG_ M2I_Byrack_SysABStTm_IMM28_27 : 40|16@1+ (0.01,0) [0|655.35] "s"  IMM
 SG_ Reserved_27 : 56|8@1+ (1,0) [0|255] ""  IMM

BO_ 2332114092 M2I_Byrack_SUMDATA28__28: 8 MBMU
 SG_ CRC_M2I_Byrack_IMM28_28 : 0|8@1+ (1,0) [0|255] ""  IMM
 SG_ M2I_Byrack_HVS_IMM28_28 : 8|16@1+ (0.1,0) [0|6553.5] "v"  IMM
 SG_ M2I_Byrack_Enable_IMM28_28 : 24|2@1+ (1,0) [0|3] ""  IMM
 SG_ M2I_Byrack_ReVeEnable_IMM28_28 : 26|2@1+ (1,0) [0|3] ""  IMM
 SG_ Reserved_28 : 28|4@1+ (1,0) [0|15] ""  IMM
 SG_ M2I_Byrack_IsPostTm_IMM28_28 : 32|8@1+ (0.01,0) [0|2.55] "s"  IMM
 SG_ M2I_Byrack_SysABStTm_IMM28_28 : 40|16@1+ (0.01,0) [0|655.35] "s"  IMM
 SG_ Reserved_28 : 56|8@1+ (1,0) [0|255] ""  IMM

BO_ 2332114093 M2I_Byrack_SUMDATA28__29: 8 MBMU
 SG_ CRC_M2I_Byrack_IMM28_29 : 0|8@1+ (1,0) [0|255] ""  IMM
 SG_ M2I_Byrack_HVS_IMM28_29 : 8|16@1+ (0.1,0) [0|6553.5] "v"  IMM
 SG_ M2I_Byrack_Enable_IMM28_29 : 24|2@1+ (1,0) [0|3] ""  IMM
 SG_ M2I_Byrack_ReVeEnable_IMM28_29 : 26|2@1+ (1,0) [0|3] ""  IMM
 SG_ Reserved_29 : 28|4@1+ (1,0) [0|15] ""  IMM
 SG_ M2I_Byrack_IsPostTm_IMM28_29 : 32|8@1+ (0.01,0) [0|2.55] "s"  IMM
 SG_ M2I_Byrack_SysABStTm_IMM28_29 : 40|16@1+ (0.01,0) [0|655.35] "s"  IMM
 SG_ Reserved_29 : 56|8@1+ (1,0) [0|255] ""  IMM

BO_ 2332114094 M2I_Byrack_SUMDATA28__30: 8 MBMU
 SG_ CRC_M2I_Byrack_IMM28_30 : 0|8@1+ (1,0) [0|255] ""  IMM
 SG_ M2I_Byrack_HVS_IMM28_30 : 8|16@1+ (0.1,0) [0|6553.5] "v"  IMM
 SG_ M2I_Byrack_Enable_IMM28_30 : 24|2@1+ (1,0) [0|3] ""  IMM
 SG_ M2I_Byrack_ReVeEnable_IMM28_30 : 26|2@1+ (1,0) [0|3] ""  IMM
 SG_ Reserved_30 : 28|4@1+ (1,0) [0|15] ""  IMM
 SG_ M2I_Byrack_IsPostTm_IMM28_30 : 32|8@1+ (0.01,0) [0|2.55] "s"  IMM
 SG_ M2I_Byrack_SysABStTm_IMM28_30 : 40|16@1+ (0.01,0) [0|655.35] "s"  IMM
 SG_ Reserved_30 : 56|8@1+ (1,0) [0|255] ""  IMM

BO_ 2332114095 M2I_Byrack_SUMDATA28__31: 8 MBMU
 SG_ CRC_M2I_Byrack_IMM28_31 : 0|8@1+ (1,0) [0|255] ""  IMM
 SG_ M2I_Byrack_HVS_IMM28_31 : 8|16@1+ (0.1,0) [0|6553.5] "v"  IMM
 SG_ M2I_Byrack_Enable_IMM28_31 : 24|2@1+ (1,0) [0|3] ""  IMM
 SG_ M2I_Byrack_ReVeEnable_IMM28_31 : 26|2@1+ (1,0) [0|3] ""  IMM
 SG_ Reserved_31 : 28|4@1+ (1,0) [0|15] ""  IMM
 SG_ M2I_Byrack_IsPostTm_IMM28_31 : 32|8@1+ (0.01,0) [0|2.55] "s"  IMM
 SG_ M2I_Byrack_SysABStTm_IMM28_31 : 40|16@1+ (0.01,0) [0|655.35] "s"  IMM
 SG_ Reserved_31 : 56|8@1+ (1,0) [0|255] ""  IMM

BO_ 2332114321 M2I_Byrack_SUMDATA29__01: 8 MBMU
 SG_ CRC_M2I_Byrack_IMM29_01 : 0|8@1+ (1,0) [0|255] ""  IMM
 SG_ M2I_Byrack_HVS_IMM29_01 : 8|16@1+ (0.1,0) [0|6553.5] "v"  IMM
 SG_ M2I_Byrack_Enable_IMM29_01 : 24|2@1+ (1,0) [0|3] ""  IMM
 SG_ M2I_Byrack_ReVeEnable_IMM29_01 : 26|2@1+ (1,0) [0|3] ""  IMM
 SG_ Reserved_01 : 28|4@1+ (1,0) [0|15] ""  IMM
 SG_ M2I_Byrack_IsPostTm_IMM29_01 : 32|8@1+ (0.01,0) [0|2.55] "s"  IMM
 SG_ M2I_Byrack_SysABStTm_IMM29_01 : 40|16@1+ (0.01,0) [0|655.35] "s"  IMM
 SG_ Reserved_01 : 56|8@1+ (1,0) [0|255] ""  IMM

BO_ 2332114322 M2I_Byrack_SUMDATA29__02: 8 MBMU
 SG_ CRC_M2I_Byrack_IMM29_02 : 0|8@1+ (1,0) [0|255] ""  IMM
 SG_ M2I_Byrack_HVS_IMM29_02 : 8|16@1+ (0.1,0) [0|6553.5] "v"  IMM
 SG_ M2I_Byrack_Enable_IMM29_02 : 24|2@1+ (1,0) [0|3] ""  IMM
 SG_ M2I_Byrack_ReVeEnable_IMM29_02 : 26|2@1+ (1,0) [0|3] ""  IMM
 SG_ Reserved_02 : 28|4@1+ (1,0) [0|15] ""  IMM
 SG_ M2I_Byrack_IsPostTm_IMM29_02 : 32|8@1+ (0.01,0) [0|2.55] "s"  IMM
 SG_ M2I_Byrack_SysABStTm_IMM29_02 : 40|16@1+ (0.01,0) [0|655.35] "s"  IMM
 SG_ Reserved_02 : 56|8@1+ (1,0) [0|255] ""  IMM

BO_ 2332114323 M2I_Byrack_SUMDATA29__03: 8 MBMU
 SG_ CRC_M2I_Byrack_IMM29_03 : 0|8@1+ (1,0) [0|255] ""  IMM
 SG_ M2I_Byrack_HVS_IMM29_03 : 8|16@1+ (0.1,0) [0|6553.5] "v"  IMM
 SG_ M2I_Byrack_Enable_IMM29_03 : 24|2@1+ (1,0) [0|3] ""  IMM
 SG_ M2I_Byrack_ReVeEnable_IMM29_03 : 26|2@1+ (1,0) [0|3] ""  IMM
 SG_ Reserved_03 : 28|4@1+ (1,0) [0|15] ""  IMM
 SG_ M2I_Byrack_IsPostTm_IMM29_03 : 32|8@1+ (0.01,0) [0|2.55] "s"  IMM
 SG_ M2I_Byrack_SysABStTm_IMM29_03 : 40|16@1+ (0.01,0) [0|655.35] "s"  IMM
 SG_ Reserved_03 : 56|8@1+ (1,0) [0|255] ""  IMM

BO_ 2332114324 M2I_Byrack_SUMDATA29__04: 8 MBMU
 SG_ CRC_M2I_Byrack_IMM29_04 : 0|8@1+ (1,0) [0|255] ""  IMM
 SG_ M2I_Byrack_HVS_IMM29_04 : 8|16@1+ (0.1,0) [0|6553.5] "v"  IMM
 SG_ M2I_Byrack_Enable_IMM29_04 : 24|2@1+ (1,0) [0|3] ""  IMM
 SG_ M2I_Byrack_ReVeEnable_IMM29_04 : 26|2@1+ (1,0) [0|3] ""  IMM
 SG_ Reserved_04 : 28|4@1+ (1,0) [0|15] ""  IMM
 SG_ M2I_Byrack_IsPostTm_IMM29_04 : 32|8@1+ (0.01,0) [0|2.55] "s"  IMM
 SG_ M2I_Byrack_SysABStTm_IMM29_04 : 40|16@1+ (0.01,0) [0|655.35] "s"  IMM
 SG_ Reserved_04 : 56|8@1+ (1,0) [0|255] ""  IMM

BO_ 2332114325 M2I_Byrack_SUMDATA29__05: 8 MBMU
 SG_ CRC_M2I_Byrack_IMM29_05 : 0|8@1+ (1,0) [0|255] ""  IMM
 SG_ M2I_Byrack_HVS_IMM29_05 : 8|16@1+ (0.1,0) [0|6553.5] "v"  IMM
 SG_ M2I_Byrack_Enable_IMM29_05 : 24|2@1+ (1,0) [0|3] ""  IMM
 SG_ M2I_Byrack_ReVeEnable_IMM29_05 : 26|2@1+ (1,0) [0|3] ""  IMM
 SG_ Reserved_05 : 28|4@1+ (1,0) [0|15] ""  IMM
 SG_ M2I_Byrack_IsPostTm_IMM29_05 : 32|8@1+ (0.01,0) [0|2.55] "s"  IMM
 SG_ M2I_Byrack_SysABStTm_IMM29_05 : 40|16@1+ (0.01,0) [0|655.35] "s"  IMM
 SG_ Reserved_05 : 56|8@1+ (1,0) [0|255] ""  IMM

BO_ 2332114326 M2I_Byrack_SUMDATA29__06: 8 MBMU
 SG_ CRC_M2I_Byrack_IMM29_06 : 0|8@1+ (1,0) [0|255] ""  IMM
 SG_ M2I_Byrack_HVS_IMM29_06 : 8|16@1+ (0.1,0) [0|6553.5] "v"  IMM
 SG_ M2I_Byrack_Enable_IMM29_06 : 24|2@1+ (1,0) [0|3] ""  IMM
 SG_ M2I_Byrack_ReVeEnable_IMM29_06 : 26|2@1+ (1,0) [0|3] ""  IMM
 SG_ Reserved_06 : 28|4@1+ (1,0) [0|15] ""  IMM
 SG_ M2I_Byrack_IsPostTm_IMM29_06 : 32|8@1+ (0.01,0) [0|2.55] "s"  IMM
 SG_ M2I_Byrack_SysABStTm_IMM29_06 : 40|16@1+ (0.01,0) [0|655.35] "s"  IMM
 SG_ Reserved_06 : 56|8@1+ (1,0) [0|255] ""  IMM

BO_ 2332114327 M2I_Byrack_SUMDATA29__07: 8 MBMU
 SG_ CRC_M2I_Byrack_IMM29_07 : 0|8@1+ (1,0) [0|255] ""  IMM
 SG_ M2I_Byrack_HVS_IMM29_07 : 8|16@1+ (0.1,0) [0|6553.5] "v"  IMM
 SG_ M2I_Byrack_Enable_IMM29_07 : 24|2@1+ (1,0) [0|3] ""  IMM
 SG_ M2I_Byrack_ReVeEnable_IMM29_07 : 26|2@1+ (1,0) [0|3] ""  IMM
 SG_ Reserved_07 : 28|4@1+ (1,0) [0|15] ""  IMM
 SG_ M2I_Byrack_IsPostTm_IMM29_07 : 32|8@1+ (0.01,0) [0|2.55] "s"  IMM
 SG_ M2I_Byrack_SysABStTm_IMM29_07 : 40|16@1+ (0.01,0) [0|655.35] "s"  IMM
 SG_ Reserved_07 : 56|8@1+ (1,0) [0|255] ""  IMM

BO_ 2332114328 M2I_Byrack_SUMDATA29__08: 8 MBMU
 SG_ CRC_M2I_Byrack_IMM29_08 : 0|8@1+ (1,0) [0|255] ""  IMM
 SG_ M2I_Byrack_HVS_IMM29_08 : 8|16@1+ (0.1,0) [0|6553.5] "v"  IMM
 SG_ M2I_Byrack_Enable_IMM29_08 : 24|2@1+ (1,0) [0|3] ""  IMM
 SG_ M2I_Byrack_ReVeEnable_IMM29_08 : 26|2@1+ (1,0) [0|3] ""  IMM
 SG_ Reserved_08 : 28|4@1+ (1,0) [0|15] ""  IMM
 SG_ M2I_Byrack_IsPostTm_IMM29_08 : 32|8@1+ (0.01,0) [0|2.55] "s"  IMM
 SG_ M2I_Byrack_SysABStTm_IMM29_08 : 40|16@1+ (0.01,0) [0|655.35] "s"  IMM
 SG_ Reserved_08 : 56|8@1+ (1,0) [0|255] ""  IMM

BO_ 2332114329 M2I_Byrack_SUMDATA29__09: 8 MBMU
 SG_ CRC_M2I_Byrack_IMM29_09 : 0|8@1+ (1,0) [0|255] ""  IMM
 SG_ M2I_Byrack_HVS_IMM29_09 : 8|16@1+ (0.1,0) [0|6553.5] "v"  IMM
 SG_ M2I_Byrack_Enable_IMM29_09 : 24|2@1+ (1,0) [0|3] ""  IMM
 SG_ M2I_Byrack_ReVeEnable_IMM29_09 : 26|2@1+ (1,0) [0|3] ""  IMM
 SG_ Reserved_09 : 28|4@1+ (1,0) [0|15] ""  IMM
 SG_ M2I_Byrack_IsPostTm_IMM29_09 : 32|8@1+ (0.01,0) [0|2.55] "s"  IMM
 SG_ M2I_Byrack_SysABStTm_IMM29_09 : 40|16@1+ (0.01,0) [0|655.35] "s"  IMM
 SG_ Reserved_09 : 56|8@1+ (1,0) [0|255] ""  IMM

BO_ 2332114330 M2I_Byrack_SUMDATA29__10: 8 MBMU
 SG_ CRC_M2I_Byrack_IMM29_10 : 0|8@1+ (1,0) [0|255] ""  IMM
 SG_ M2I_Byrack_HVS_IMM29_10 : 8|16@1+ (0.1,0) [0|6553.5] "v"  IMM
 SG_ M2I_Byrack_Enable_IMM29_10 : 24|2@1+ (1,0) [0|3] ""  IMM
 SG_ M2I_Byrack_ReVeEnable_IMM29_10 : 26|2@1+ (1,0) [0|3] ""  IMM
 SG_ Reserved_10 : 28|4@1+ (1,0) [0|15] ""  IMM
 SG_ M2I_Byrack_IsPostTm_IMM29_10 : 32|8@1+ (0.01,0) [0|2.55] "s"  IMM
 SG_ M2I_Byrack_SysABStTm_IMM29_10 : 40|16@1+ (0.01,0) [0|655.35] "s"  IMM
 SG_ Reserved_10 : 56|8@1+ (1,0) [0|255] ""  IMM

BO_ 2332114331 M2I_Byrack_SUMDATA29__11: 8 MBMU
 SG_ CRC_M2I_Byrack_IMM29_11 : 0|8@1+ (1,0) [0|255] ""  IMM
 SG_ M2I_Byrack_HVS_IMM29_11 : 8|16@1+ (0.1,0) [0|6553.5] "v"  IMM
 SG_ M2I_Byrack_Enable_IMM29_11 : 24|2@1+ (1,0) [0|3] ""  IMM
 SG_ M2I_Byrack_ReVeEnable_IMM29_11 : 26|2@1+ (1,0) [0|3] ""  IMM
 SG_ Reserved_11 : 28|4@1+ (1,0) [0|15] ""  IMM
 SG_ M2I_Byrack_IsPostTm_IMM29_11 : 32|8@1+ (0.01,0) [0|2.55] "s"  IMM
 SG_ M2I_Byrack_SysABStTm_IMM29_11 : 40|16@1+ (0.01,0) [0|655.35] "s"  IMM
 SG_ Reserved_11 : 56|8@1+ (1,0) [0|255] ""  IMM

BO_ 2332114332 M2I_Byrack_SUMDATA29__12: 8 MBMU
 SG_ CRC_M2I_Byrack_IMM29_12 : 0|8@1+ (1,0) [0|255] ""  IMM
 SG_ M2I_Byrack_HVS_IMM29_12 : 8|16@1+ (0.1,0) [0|6553.5] "v"  IMM
 SG_ M2I_Byrack_Enable_IMM29_12 : 24|2@1+ (1,0) [0|3] ""  IMM
 SG_ M2I_Byrack_ReVeEnable_IMM29_12 : 26|2@1+ (1,0) [0|3] ""  IMM
 SG_ Reserved_12 : 28|4@1+ (1,0) [0|15] ""  IMM
 SG_ M2I_Byrack_IsPostTm_IMM29_12 : 32|8@1+ (0.01,0) [0|2.55] "s"  IMM
 SG_ M2I_Byrack_SysABStTm_IMM29_12 : 40|16@1+ (0.01,0) [0|655.35] "s"  IMM
 SG_ Reserved_12 : 56|8@1+ (1,0) [0|255] ""  IMM

BO_ 2332114333 M2I_Byrack_SUMDATA29__13: 8 MBMU
 SG_ CRC_M2I_Byrack_IMM29_13 : 0|8@1+ (1,0) [0|255] ""  IMM
 SG_ M2I_Byrack_HVS_IMM29_13 : 8|16@1+ (0.1,0) [0|6553.5] "v"  IMM
 SG_ M2I_Byrack_Enable_IMM29_13 : 24|2@1+ (1,0) [0|3] ""  IMM
 SG_ M2I_Byrack_ReVeEnable_IMM29_13 : 26|2@1+ (1,0) [0|3] ""  IMM
 SG_ Reserved_13 : 28|4@1+ (1,0) [0|15] ""  IMM
 SG_ M2I_Byrack_IsPostTm_IMM29_13 : 32|8@1+ (0.01,0) [0|2.55] "s"  IMM
 SG_ M2I_Byrack_SysABStTm_IMM29_13 : 40|16@1+ (0.01,0) [0|655.35] "s"  IMM
 SG_ Reserved_13 : 56|8@1+ (1,0) [0|255] ""  IMM

BO_ 2332114334 M2I_Byrack_SUMDATA29__14: 8 MBMU
 SG_ CRC_M2I_Byrack_IMM29_14 : 0|8@1+ (1,0) [0|255] ""  IMM
 SG_ M2I_Byrack_HVS_IMM29_14 : 8|16@1+ (0.1,0) [0|6553.5] "v"  IMM
 SG_ M2I_Byrack_Enable_IMM29_14 : 24|2@1+ (1,0) [0|3] ""  IMM
 SG_ M2I_Byrack_ReVeEnable_IMM29_14 : 26|2@1+ (1,0) [0|3] ""  IMM
 SG_ Reserved_14 : 28|4@1+ (1,0) [0|15] ""  IMM
 SG_ M2I_Byrack_IsPostTm_IMM29_14 : 32|8@1+ (0.01,0) [0|2.55] "s"  IMM
 SG_ M2I_Byrack_SysABStTm_IMM29_14 : 40|16@1+ (0.01,0) [0|655.35] "s"  IMM
 SG_ Reserved_14 : 56|8@1+ (1,0) [0|255] ""  IMM

BO_ 2332114335 M2I_Byrack_SUMDATA29__15: 8 MBMU
 SG_ CRC_M2I_Byrack_IMM29_15 : 0|8@1+ (1,0) [0|255] ""  IMM
 SG_ M2I_Byrack_HVS_IMM29_15 : 8|16@1+ (0.1,0) [0|6553.5] "v"  IMM
 SG_ M2I_Byrack_Enable_IMM29_15 : 24|2@1+ (1,0) [0|3] ""  IMM
 SG_ M2I_Byrack_ReVeEnable_IMM29_15 : 26|2@1+ (1,0) [0|3] ""  IMM
 SG_ Reserved_15 : 28|4@1+ (1,0) [0|15] ""  IMM
 SG_ M2I_Byrack_IsPostTm_IMM29_15 : 32|8@1+ (0.01,0) [0|2.55] "s"  IMM
 SG_ M2I_Byrack_SysABStTm_IMM29_15 : 40|16@1+ (0.01,0) [0|655.35] "s"  IMM
 SG_ Reserved_15 : 56|8@1+ (1,0) [0|255] ""  IMM

BO_ 2332114336 M2I_Byrack_SUMDATA29__16: 8 MBMU
 SG_ CRC_M2I_Byrack_IMM29_16 : 0|8@1+ (1,0) [0|255] ""  IMM
 SG_ M2I_Byrack_HVS_IMM29_16 : 8|16@1+ (0.1,0) [0|6553.5] "v"  IMM
 SG_ M2I_Byrack_Enable_IMM29_16 : 24|2@1+ (1,0) [0|3] ""  IMM
 SG_ M2I_Byrack_ReVeEnable_IMM29_16 : 26|2@1+ (1,0) [0|3] ""  IMM
 SG_ Reserved_16 : 28|4@1+ (1,0) [0|15] ""  IMM
 SG_ M2I_Byrack_IsPostTm_IMM29_16 : 32|8@1+ (0.01,0) [0|2.55] "s"  IMM
 SG_ M2I_Byrack_SysABStTm_IMM29_16 : 40|16@1+ (0.01,0) [0|655.35] "s"  IMM
 SG_ Reserved_16 : 56|8@1+ (1,0) [0|255] ""  IMM

BO_ 2332114337 M2I_Byrack_SUMDATA29__17: 8 MBMU
 SG_ CRC_M2I_Byrack_IMM29_17 : 0|8@1+ (1,0) [0|255] ""  IMM
 SG_ M2I_Byrack_HVS_IMM29_17 : 8|16@1+ (0.1,0) [0|6553.5] "v"  IMM
 SG_ M2I_Byrack_Enable_IMM29_17 : 24|2@1+ (1,0) [0|3] ""  IMM
 SG_ M2I_Byrack_ReVeEnable_IMM29_17 : 26|2@1+ (1,0) [0|3] ""  IMM
 SG_ Reserved_17 : 28|4@1+ (1,0) [0|15] ""  IMM
 SG_ M2I_Byrack_IsPostTm_IMM29_17 : 32|8@1+ (0.01,0) [0|2.55] "s"  IMM
 SG_ M2I_Byrack_SysABStTm_IMM29_17 : 40|16@1+ (0.01,0) [0|655.35] "s"  IMM
 SG_ Reserved_17 : 56|8@1+ (1,0) [0|255] ""  IMM

BO_ 2332114338 M2I_Byrack_SUMDATA29__18: 8 MBMU
 SG_ CRC_M2I_Byrack_IMM29_18 : 0|8@1+ (1,0) [0|255] ""  IMM
 SG_ M2I_Byrack_HVS_IMM29_18 : 8|16@1+ (0.1,0) [0|6553.5] "v"  IMM
 SG_ M2I_Byrack_Enable_IMM29_18 : 24|2@1+ (1,0) [0|3] ""  IMM
 SG_ M2I_Byrack_ReVeEnable_IMM29_18 : 26|2@1+ (1,0) [0|3] ""  IMM
 SG_ Reserved_18 : 28|4@1+ (1,0) [0|15] ""  IMM
 SG_ M2I_Byrack_IsPostTm_IMM29_18 : 32|8@1+ (0.01,0) [0|2.55] "s"  IMM
 SG_ M2I_Byrack_SysABStTm_IMM29_18 : 40|16@1+ (0.01,0) [0|655.35] "s"  IMM
 SG_ Reserved_18 : 56|8@1+ (1,0) [0|255] ""  IMM

BO_ 2332114339 M2I_Byrack_SUMDATA29__19: 8 MBMU
 SG_ CRC_M2I_Byrack_IMM29_19 : 0|8@1+ (1,0) [0|255] ""  IMM
 SG_ M2I_Byrack_HVS_IMM29_19 : 8|16@1+ (0.1,0) [0|6553.5] "v"  IMM
 SG_ M2I_Byrack_Enable_IMM29_19 : 24|2@1+ (1,0) [0|3] ""  IMM
 SG_ M2I_Byrack_ReVeEnable_IMM29_19 : 26|2@1+ (1,0) [0|3] ""  IMM
 SG_ Reserved_19 : 28|4@1+ (1,0) [0|15] ""  IMM
 SG_ M2I_Byrack_IsPostTm_IMM29_19 : 32|8@1+ (0.01,0) [0|2.55] "s"  IMM
 SG_ M2I_Byrack_SysABStTm_IMM29_19 : 40|16@1+ (0.01,0) [0|655.35] "s"  IMM
 SG_ Reserved_19 : 56|8@1+ (1,0) [0|255] ""  IMM

BO_ 2332114340 M2I_Byrack_SUMDATA29__20: 8 MBMU
 SG_ CRC_M2I_Byrack_IMM29_20 : 0|8@1+ (1,0) [0|255] ""  IMM
 SG_ M2I_Byrack_HVS_IMM29_20 : 8|16@1+ (0.1,0) [0|6553.5] "v"  IMM
 SG_ M2I_Byrack_Enable_IMM29_20 : 24|2@1+ (1,0) [0|3] ""  IMM
 SG_ M2I_Byrack_ReVeEnable_IMM29_20 : 26|2@1+ (1,0) [0|3] ""  IMM
 SG_ Reserved_20 : 28|4@1+ (1,0) [0|15] ""  IMM
 SG_ M2I_Byrack_IsPostTm_IMM29_20 : 32|8@1+ (0.01,0) [0|2.55] "s"  IMM
 SG_ M2I_Byrack_SysABStTm_IMM29_20 : 40|16@1+ (0.01,0) [0|655.35] "s"  IMM
 SG_ Reserved_20 : 56|8@1+ (1,0) [0|255] ""  IMM

BO_ 2332114341 M2I_Byrack_SUMDATA29__21: 8 MBMU
 SG_ CRC_M2I_Byrack_IMM29_21 : 0|8@1+ (1,0) [0|255] ""  IMM
 SG_ M2I_Byrack_HVS_IMM29_21 : 8|16@1+ (0.1,0) [0|6553.5] "v"  IMM
 SG_ M2I_Byrack_Enable_IMM29_21 : 24|2@1+ (1,0) [0|3] ""  IMM
 SG_ M2I_Byrack_ReVeEnable_IMM29_21 : 26|2@1+ (1,0) [0|3] ""  IMM
 SG_ Reserved_21 : 28|4@1+ (1,0) [0|15] ""  IMM
 SG_ M2I_Byrack_IsPostTm_IMM29_21 : 32|8@1+ (0.01,0) [0|2.55] "s"  IMM
 SG_ M2I_Byrack_SysABStTm_IMM29_21 : 40|16@1+ (0.01,0) [0|655.35] "s"  IMM
 SG_ Reserved_21 : 56|8@1+ (1,0) [0|255] ""  IMM

BO_ 2332114342 M2I_Byrack_SUMDATA29__22: 8 MBMU
 SG_ CRC_M2I_Byrack_IMM29_22 : 0|8@1+ (1,0) [0|255] ""  IMM
 SG_ M2I_Byrack_HVS_IMM29_22 : 8|16@1+ (0.1,0) [0|6553.5] "v"  IMM
 SG_ M2I_Byrack_Enable_IMM29_22 : 24|2@1+ (1,0) [0|3] ""  IMM
 SG_ M2I_Byrack_ReVeEnable_IMM29_22 : 26|2@1+ (1,0) [0|3] ""  IMM
 SG_ Reserved_22 : 28|4@1+ (1,0) [0|15] ""  IMM
 SG_ M2I_Byrack_IsPostTm_IMM29_22 : 32|8@1+ (0.01,0) [0|2.55] "s"  IMM
 SG_ M2I_Byrack_SysABStTm_IMM29_22 : 40|16@1+ (0.01,0) [0|655.35] "s"  IMM
 SG_ Reserved_22 : 56|8@1+ (1,0) [0|255] ""  IMM

BO_ 2332114343 M2I_Byrack_SUMDATA29__23: 8 MBMU
 SG_ CRC_M2I_Byrack_IMM29_23 : 0|8@1+ (1,0) [0|255] ""  IMM
 SG_ M2I_Byrack_HVS_IMM29_23 : 8|16@1+ (0.1,0) [0|6553.5] "v"  IMM
 SG_ M2I_Byrack_Enable_IMM29_23 : 24|2@1+ (1,0) [0|3] ""  IMM
 SG_ M2I_Byrack_ReVeEnable_IMM29_23 : 26|2@1+ (1,0) [0|3] ""  IMM
 SG_ Reserved_23 : 28|4@1+ (1,0) [0|15] ""  IMM
 SG_ M2I_Byrack_IsPostTm_IMM29_23 : 32|8@1+ (0.01,0) [0|2.55] "s"  IMM
 SG_ M2I_Byrack_SysABStTm_IMM29_23 : 40|16@1+ (0.01,0) [0|655.35] "s"  IMM
 SG_ Reserved_23 : 56|8@1+ (1,0) [0|255] ""  IMM

BO_ 2332114344 M2I_Byrack_SUMDATA29__24: 8 MBMU
 SG_ CRC_M2I_Byrack_IMM29_24 : 0|8@1+ (1,0) [0|255] ""  IMM
 SG_ M2I_Byrack_HVS_IMM29_24 : 8|16@1+ (0.1,0) [0|6553.5] "v"  IMM
 SG_ M2I_Byrack_Enable_IMM29_24 : 24|2@1+ (1,0) [0|3] ""  IMM
 SG_ M2I_Byrack_ReVeEnable_IMM29_24 : 26|2@1+ (1,0) [0|3] ""  IMM
 SG_ Reserved_24 : 28|4@1+ (1,0) [0|15] ""  IMM
 SG_ M2I_Byrack_IsPostTm_IMM29_24 : 32|8@1+ (0.01,0) [0|2.55] "s"  IMM
 SG_ M2I_Byrack_SysABStTm_IMM29_24 : 40|16@1+ (0.01,0) [0|655.35] "s"  IMM
 SG_ Reserved_24 : 56|8@1+ (1,0) [0|255] ""  IMM

BO_ 2332114345 M2I_Byrack_SUMDATA29__25: 8 MBMU
 SG_ CRC_M2I_Byrack_IMM29_25 : 0|8@1+ (1,0) [0|255] ""  IMM
 SG_ M2I_Byrack_HVS_IMM29_25 : 8|16@1+ (0.1,0) [0|6553.5] "v"  IMM
 SG_ M2I_Byrack_Enable_IMM29_25 : 24|2@1+ (1,0) [0|3] ""  IMM
 SG_ M2I_Byrack_ReVeEnable_IMM29_25 : 26|2@1+ (1,0) [0|3] ""  IMM
 SG_ Reserved_25 : 28|4@1+ (1,0) [0|15] ""  IMM
 SG_ M2I_Byrack_IsPostTm_IMM29_25 : 32|8@1+ (0.01,0) [0|2.55] "s"  IMM
 SG_ M2I_Byrack_SysABStTm_IMM29_25 : 40|16@1+ (0.01,0) [0|655.35] "s"  IMM
 SG_ Reserved_25 : 56|8@1+ (1,0) [0|255] ""  IMM

BO_ 2332114346 M2I_Byrack_SUMDATA29__26: 8 MBMU
 SG_ CRC_M2I_Byrack_IMM29_26 : 0|8@1+ (1,0) [0|255] ""  IMM
 SG_ M2I_Byrack_HVS_IMM29_26 : 8|16@1+ (0.1,0) [0|6553.5] "v"  IMM
 SG_ M2I_Byrack_Enable_IMM29_26 : 24|2@1+ (1,0) [0|3] ""  IMM
 SG_ M2I_Byrack_ReVeEnable_IMM29_26 : 26|2@1+ (1,0) [0|3] ""  IMM
 SG_ Reserved_26 : 28|4@1+ (1,0) [0|15] ""  IMM
 SG_ M2I_Byrack_IsPostTm_IMM29_26 : 32|8@1+ (0.01,0) [0|2.55] "s"  IMM
 SG_ M2I_Byrack_SysABStTm_IMM29_26 : 40|16@1+ (0.01,0) [0|655.35] "s"  IMM
 SG_ Reserved_26 : 56|8@1+ (1,0) [0|255] ""  IMM

BO_ 2332114347 M2I_Byrack_SUMDATA29__27: 8 MBMU
 SG_ CRC_M2I_Byrack_IMM29_27 : 0|8@1+ (1,0) [0|255] ""  IMM
 SG_ M2I_Byrack_HVS_IMM29_27 : 8|16@1+ (0.1,0) [0|6553.5] "v"  IMM
 SG_ M2I_Byrack_Enable_IMM29_27 : 24|2@1+ (1,0) [0|3] ""  IMM
 SG_ M2I_Byrack_ReVeEnable_IMM29_27 : 26|2@1+ (1,0) [0|3] ""  IMM
 SG_ Reserved_27 : 28|4@1+ (1,0) [0|15] ""  IMM
 SG_ M2I_Byrack_IsPostTm_IMM29_27 : 32|8@1+ (0.01,0) [0|2.55] "s"  IMM
 SG_ M2I_Byrack_SysABStTm_IMM29_27 : 40|16@1+ (0.01,0) [0|655.35] "s"  IMM
 SG_ Reserved_27 : 56|8@1+ (1,0) [0|255] ""  IMM

BO_ 2332114348 M2I_Byrack_SUMDATA29__28: 8 MBMU
 SG_ CRC_M2I_Byrack_IMM29_28 : 0|8@1+ (1,0) [0|255] ""  IMM
 SG_ M2I_Byrack_HVS_IMM29_28 : 8|16@1+ (0.1,0) [0|6553.5] "v"  IMM
 SG_ M2I_Byrack_Enable_IMM29_28 : 24|2@1+ (1,0) [0|3] ""  IMM
 SG_ M2I_Byrack_ReVeEnable_IMM29_28 : 26|2@1+ (1,0) [0|3] ""  IMM
 SG_ Reserved_28 : 28|4@1+ (1,0) [0|15] ""  IMM
 SG_ M2I_Byrack_IsPostTm_IMM29_28 : 32|8@1+ (0.01,0) [0|2.55] "s"  IMM
 SG_ M2I_Byrack_SysABStTm_IMM29_28 : 40|16@1+ (0.01,0) [0|655.35] "s"  IMM
 SG_ Reserved_28 : 56|8@1+ (1,0) [0|255] ""  IMM

BO_ 2332114349 M2I_Byrack_SUMDATA29__29: 8 MBMU
 SG_ CRC_M2I_Byrack_IMM29_29 : 0|8@1+ (1,0) [0|255] ""  IMM
 SG_ M2I_Byrack_HVS_IMM29_29 : 8|16@1+ (0.1,0) [0|6553.5] "v"  IMM
 SG_ M2I_Byrack_Enable_IMM29_29 : 24|2@1+ (1,0) [0|3] ""  IMM
 SG_ M2I_Byrack_ReVeEnable_IMM29_29 : 26|2@1+ (1,0) [0|3] ""  IMM
 SG_ Reserved_29 : 28|4@1+ (1,0) [0|15] ""  IMM
 SG_ M2I_Byrack_IsPostTm_IMM29_29 : 32|8@1+ (0.01,0) [0|2.55] "s"  IMM
 SG_ M2I_Byrack_SysABStTm_IMM29_29 : 40|16@1+ (0.01,0) [0|655.35] "s"  IMM
 SG_ Reserved_29 : 56|8@1+ (1,0) [0|255] ""  IMM

BO_ 2332114350 M2I_Byrack_SUMDATA29__30: 8 MBMU
 SG_ CRC_M2I_Byrack_IMM29_30 : 0|8@1+ (1,0) [0|255] ""  IMM
 SG_ M2I_Byrack_HVS_IMM29_30 : 8|16@1+ (0.1,0) [0|6553.5] "v"  IMM
 SG_ M2I_Byrack_Enable_IMM29_30 : 24|2@1+ (1,0) [0|3] ""  IMM
 SG_ M2I_Byrack_ReVeEnable_IMM29_30 : 26|2@1+ (1,0) [0|3] ""  IMM
 SG_ Reserved_30 : 28|4@1+ (1,0) [0|15] ""  IMM
 SG_ M2I_Byrack_IsPostTm_IMM29_30 : 32|8@1+ (0.01,0) [0|2.55] "s"  IMM
 SG_ M2I_Byrack_SysABStTm_IMM29_30 : 40|16@1+ (0.01,0) [0|655.35] "s"  IMM
 SG_ Reserved_30 : 56|8@1+ (1,0) [0|255] ""  IMM

BO_ 2332114351 M2I_Byrack_SUMDATA29__31: 8 MBMU
 SG_ CRC_M2I_Byrack_IMM29_31 : 0|8@1+ (1,0) [0|255] ""  IMM
 SG_ M2I_Byrack_HVS_IMM29_31 : 8|16@1+ (0.1,0) [0|6553.5] "v"  IMM
 SG_ M2I_Byrack_Enable_IMM29_31 : 24|2@1+ (1,0) [0|3] ""  IMM
 SG_ M2I_Byrack_ReVeEnable_IMM29_31 : 26|2@1+ (1,0) [0|3] ""  IMM
 SG_ Reserved_31 : 28|4@1+ (1,0) [0|15] ""  IMM
 SG_ M2I_Byrack_IsPostTm_IMM29_31 : 32|8@1+ (0.01,0) [0|2.55] "s"  IMM
 SG_ M2I_Byrack_SysABStTm_IMM29_31 : 40|16@1+ (0.01,0) [0|655.35] "s"  IMM
 SG_ Reserved_31 : 56|8@1+ (1,0) [0|255] ""  IMM

BO_ 2332114577 M2I_Byrack_SUMDATA30__01: 8 MBMU
 SG_ CRC_M2I_Byrack_IMM30_01 : 0|8@1+ (1,0) [0|255] ""  IMM
 SG_ M2I_Byrack_HVS_IMM30_01 : 8|16@1+ (0.1,0) [0|6553.5] "v"  IMM
 SG_ M2I_Byrack_Enable_IMM30_01 : 24|2@1+ (1,0) [0|3] ""  IMM
 SG_ M2I_Byrack_ReVeEnable_IMM30_01 : 26|2@1+ (1,0) [0|3] ""  IMM
 SG_ Reserved_01 : 28|4@1+ (1,0) [0|15] ""  IMM
 SG_ M2I_Byrack_IsPostTm_IMM30_01 : 32|8@1+ (0.01,0) [0|2.55] "s"  IMM
 SG_ M2I_Byrack_SysABStTm_IMM30_01 : 40|16@1+ (0.01,0) [0|655.35] "s"  IMM
 SG_ Reserved_01 : 56|8@1+ (1,0) [0|255] ""  IMM

BO_ 2332114578 M2I_Byrack_SUMDATA30__02: 8 MBMU
 SG_ CRC_M2I_Byrack_IMM30_02 : 0|8@1+ (1,0) [0|255] ""  IMM
 SG_ M2I_Byrack_HVS_IMM30_02 : 8|16@1+ (0.1,0) [0|6553.5] "v"  IMM
 SG_ M2I_Byrack_Enable_IMM30_02 : 24|2@1+ (1,0) [0|3] ""  IMM
 SG_ M2I_Byrack_ReVeEnable_IMM30_02 : 26|2@1+ (1,0) [0|3] ""  IMM
 SG_ Reserved_02 : 28|4@1+ (1,0) [0|15] ""  IMM
 SG_ M2I_Byrack_IsPostTm_IMM30_02 : 32|8@1+ (0.01,0) [0|2.55] "s"  IMM
 SG_ M2I_Byrack_SysABStTm_IMM30_02 : 40|16@1+ (0.01,0) [0|655.35] "s"  IMM
 SG_ Reserved_02 : 56|8@1+ (1,0) [0|255] ""  IMM

BO_ 2332114579 M2I_Byrack_SUMDATA30__03: 8 MBMU
 SG_ CRC_M2I_Byrack_IMM30_03 : 0|8@1+ (1,0) [0|255] ""  IMM
 SG_ M2I_Byrack_HVS_IMM30_03 : 8|16@1+ (0.1,0) [0|6553.5] "v"  IMM
 SG_ M2I_Byrack_Enable_IMM30_03 : 24|2@1+ (1,0) [0|3] ""  IMM
 SG_ M2I_Byrack_ReVeEnable_IMM30_03 : 26|2@1+ (1,0) [0|3] ""  IMM
 SG_ Reserved_03 : 28|4@1+ (1,0) [0|15] ""  IMM
 SG_ M2I_Byrack_IsPostTm_IMM30_03 : 32|8@1+ (0.01,0) [0|2.55] "s"  IMM
 SG_ M2I_Byrack_SysABStTm_IMM30_03 : 40|16@1+ (0.01,0) [0|655.35] "s"  IMM
 SG_ Reserved_03 : 56|8@1+ (1,0) [0|255] ""  IMM

BO_ 2332114580 M2I_Byrack_SUMDATA30__04: 8 MBMU
 SG_ CRC_M2I_Byrack_IMM30_04 : 0|8@1+ (1,0) [0|255] ""  IMM
 SG_ M2I_Byrack_HVS_IMM30_04 : 8|16@1+ (0.1,0) [0|6553.5] "v"  IMM
 SG_ M2I_Byrack_Enable_IMM30_04 : 24|2@1+ (1,0) [0|3] ""  IMM
 SG_ M2I_Byrack_ReVeEnable_IMM30_04 : 26|2@1+ (1,0) [0|3] ""  IMM
 SG_ Reserved_04 : 28|4@1+ (1,0) [0|15] ""  IMM
 SG_ M2I_Byrack_IsPostTm_IMM30_04 : 32|8@1+ (0.01,0) [0|2.55] "s"  IMM
 SG_ M2I_Byrack_SysABStTm_IMM30_04 : 40|16@1+ (0.01,0) [0|655.35] "s"  IMM
 SG_ Reserved_04 : 56|8@1+ (1,0) [0|255] ""  IMM

BO_ 2332114581 M2I_Byrack_SUMDATA30__05: 8 MBMU
 SG_ CRC_M2I_Byrack_IMM30_05 : 0|8@1+ (1,0) [0|255] ""  IMM
 SG_ M2I_Byrack_HVS_IMM30_05 : 8|16@1+ (0.1,0) [0|6553.5] "v"  IMM
 SG_ M2I_Byrack_Enable_IMM30_05 : 24|2@1+ (1,0) [0|3] ""  IMM
 SG_ M2I_Byrack_ReVeEnable_IMM30_05 : 26|2@1+ (1,0) [0|3] ""  IMM
 SG_ Reserved_05 : 28|4@1+ (1,0) [0|15] ""  IMM
 SG_ M2I_Byrack_IsPostTm_IMM30_05 : 32|8@1+ (0.01,0) [0|2.55] "s"  IMM
 SG_ M2I_Byrack_SysABStTm_IMM30_05 : 40|16@1+ (0.01,0) [0|655.35] "s"  IMM
 SG_ Reserved_05 : 56|8@1+ (1,0) [0|255] ""  IMM

BO_ 2332114582 M2I_Byrack_SUMDATA30__06: 8 MBMU
 SG_ CRC_M2I_Byrack_IMM30_06 : 0|8@1+ (1,0) [0|255] ""  IMM
 SG_ M2I_Byrack_HVS_IMM30_06 : 8|16@1+ (0.1,0) [0|6553.5] "v"  IMM
 SG_ M2I_Byrack_Enable_IMM30_06 : 24|2@1+ (1,0) [0|3] ""  IMM
 SG_ M2I_Byrack_ReVeEnable_IMM30_06 : 26|2@1+ (1,0) [0|3] ""  IMM
 SG_ Reserved_06 : 28|4@1+ (1,0) [0|15] ""  IMM
 SG_ M2I_Byrack_IsPostTm_IMM30_06 : 32|8@1+ (0.01,0) [0|2.55] "s"  IMM
 SG_ M2I_Byrack_SysABStTm_IMM30_06 : 40|16@1+ (0.01,0) [0|655.35] "s"  IMM
 SG_ Reserved_06 : 56|8@1+ (1,0) [0|255] ""  IMM

BO_ 2332114583 M2I_Byrack_SUMDATA30__07: 8 MBMU
 SG_ CRC_M2I_Byrack_IMM30_07 : 0|8@1+ (1,0) [0|255] ""  IMM
 SG_ M2I_Byrack_HVS_IMM30_07 : 8|16@1+ (0.1,0) [0|6553.5] "v"  IMM
 SG_ M2I_Byrack_Enable_IMM30_07 : 24|2@1+ (1,0) [0|3] ""  IMM
 SG_ M2I_Byrack_ReVeEnable_IMM30_07 : 26|2@1+ (1,0) [0|3] ""  IMM
 SG_ Reserved_07 : 28|4@1+ (1,0) [0|15] ""  IMM
 SG_ M2I_Byrack_IsPostTm_IMM30_07 : 32|8@1+ (0.01,0) [0|2.55] "s"  IMM
 SG_ M2I_Byrack_SysABStTm_IMM30_07 : 40|16@1+ (0.01,0) [0|655.35] "s"  IMM
 SG_ Reserved_07 : 56|8@1+ (1,0) [0|255] ""  IMM

BO_ 2332114584 M2I_Byrack_SUMDATA30__08: 8 MBMU
 SG_ CRC_M2I_Byrack_IMM30_08 : 0|8@1+ (1,0) [0|255] ""  IMM
 SG_ M2I_Byrack_HVS_IMM30_08 : 8|16@1+ (0.1,0) [0|6553.5] "v"  IMM
 SG_ M2I_Byrack_Enable_IMM30_08 : 24|2@1+ (1,0) [0|3] ""  IMM
 SG_ M2I_Byrack_ReVeEnable_IMM30_08 : 26|2@1+ (1,0) [0|3] ""  IMM
 SG_ Reserved_08 : 28|4@1+ (1,0) [0|15] ""  IMM
 SG_ M2I_Byrack_IsPostTm_IMM30_08 : 32|8@1+ (0.01,0) [0|2.55] "s"  IMM
 SG_ M2I_Byrack_SysABStTm_IMM30_08 : 40|16@1+ (0.01,0) [0|655.35] "s"  IMM
 SG_ Reserved_08 : 56|8@1+ (1,0) [0|255] ""  IMM

BO_ 2332114585 M2I_Byrack_SUMDATA30__09: 8 MBMU
 SG_ CRC_M2I_Byrack_IMM30_09 : 0|8@1+ (1,0) [0|255] ""  IMM
 SG_ M2I_Byrack_HVS_IMM30_09 : 8|16@1+ (0.1,0) [0|6553.5] "v"  IMM
 SG_ M2I_Byrack_Enable_IMM30_09 : 24|2@1+ (1,0) [0|3] ""  IMM
 SG_ M2I_Byrack_ReVeEnable_IMM30_09 : 26|2@1+ (1,0) [0|3] ""  IMM
 SG_ Reserved_09 : 28|4@1+ (1,0) [0|15] ""  IMM
 SG_ M2I_Byrack_IsPostTm_IMM30_09 : 32|8@1+ (0.01,0) [0|2.55] "s"  IMM
 SG_ M2I_Byrack_SysABStTm_IMM30_09 : 40|16@1+ (0.01,0) [0|655.35] "s"  IMM
 SG_ Reserved_09 : 56|8@1+ (1,0) [0|255] ""  IMM

BO_ 2332114586 M2I_Byrack_SUMDATA30__10: 8 MBMU
 SG_ CRC_M2I_Byrack_IMM30_10 : 0|8@1+ (1,0) [0|255] ""  IMM
 SG_ M2I_Byrack_HVS_IMM30_10 : 8|16@1+ (0.1,0) [0|6553.5] "v"  IMM
 SG_ M2I_Byrack_Enable_IMM30_10 : 24|2@1+ (1,0) [0|3] ""  IMM
 SG_ M2I_Byrack_ReVeEnable_IMM30_10 : 26|2@1+ (1,0) [0|3] ""  IMM
 SG_ Reserved_10 : 28|4@1+ (1,0) [0|15] ""  IMM
 SG_ M2I_Byrack_IsPostTm_IMM30_10 : 32|8@1+ (0.01,0) [0|2.55] "s"  IMM
 SG_ M2I_Byrack_SysABStTm_IMM30_10 : 40|16@1+ (0.01,0) [0|655.35] "s"  IMM
 SG_ Reserved_10 : 56|8@1+ (1,0) [0|255] ""  IMM

BO_ 2332114587 M2I_Byrack_SUMDATA30__11: 8 MBMU
 SG_ CRC_M2I_Byrack_IMM30_11 : 0|8@1+ (1,0) [0|255] ""  IMM
 SG_ M2I_Byrack_HVS_IMM30_11 : 8|16@1+ (0.1,0) [0|6553.5] "v"  IMM
 SG_ M2I_Byrack_Enable_IMM30_11 : 24|2@1+ (1,0) [0|3] ""  IMM
 SG_ M2I_Byrack_ReVeEnable_IMM30_11 : 26|2@1+ (1,0) [0|3] ""  IMM
 SG_ Reserved_11 : 28|4@1+ (1,0) [0|15] ""  IMM
 SG_ M2I_Byrack_IsPostTm_IMM30_11 : 32|8@1+ (0.01,0) [0|2.55] "s"  IMM
 SG_ M2I_Byrack_SysABStTm_IMM30_11 : 40|16@1+ (0.01,0) [0|655.35] "s"  IMM
 SG_ Reserved_11 : 56|8@1+ (1,0) [0|255] ""  IMM

BO_ 2332114588 M2I_Byrack_SUMDATA30__12: 8 MBMU
 SG_ CRC_M2I_Byrack_IMM30_12 : 0|8@1+ (1,0) [0|255] ""  IMM
 SG_ M2I_Byrack_HVS_IMM30_12 : 8|16@1+ (0.1,0) [0|6553.5] "v"  IMM
 SG_ M2I_Byrack_Enable_IMM30_12 : 24|2@1+ (1,0) [0|3] ""  IMM
 SG_ M2I_Byrack_ReVeEnable_IMM30_12 : 26|2@1+ (1,0) [0|3] ""  IMM
 SG_ Reserved_12 : 28|4@1+ (1,0) [0|15] ""  IMM
 SG_ M2I_Byrack_IsPostTm_IMM30_12 : 32|8@1+ (0.01,0) [0|2.55] "s"  IMM
 SG_ M2I_Byrack_SysABStTm_IMM30_12 : 40|16@1+ (0.01,0) [0|655.35] "s"  IMM
 SG_ Reserved_12 : 56|8@1+ (1,0) [0|255] ""  IMM

BO_ 2332114589 M2I_Byrack_SUMDATA30__13: 8 MBMU
 SG_ CRC_M2I_Byrack_IMM30_13 : 0|8@1+ (1,0) [0|255] ""  IMM
 SG_ M2I_Byrack_HVS_IMM30_13 : 8|16@1+ (0.1,0) [0|6553.5] "v"  IMM
 SG_ M2I_Byrack_Enable_IMM30_13 : 24|2@1+ (1,0) [0|3] ""  IMM
 SG_ M2I_Byrack_ReVeEnable_IMM30_13 : 26|2@1+ (1,0) [0|3] ""  IMM
 SG_ Reserved_13 : 28|4@1+ (1,0) [0|15] ""  IMM
 SG_ M2I_Byrack_IsPostTm_IMM30_13 : 32|8@1+ (0.01,0) [0|2.55] "s"  IMM
 SG_ M2I_Byrack_SysABStTm_IMM30_13 : 40|16@1+ (0.01,0) [0|655.35] "s"  IMM
 SG_ Reserved_13 : 56|8@1+ (1,0) [0|255] ""  IMM

BO_ 2332114590 M2I_Byrack_SUMDATA30__14: 8 MBMU
 SG_ CRC_M2I_Byrack_IMM30_14 : 0|8@1+ (1,0) [0|255] ""  IMM
 SG_ M2I_Byrack_HVS_IMM30_14 : 8|16@1+ (0.1,0) [0|6553.5] "v"  IMM
 SG_ M2I_Byrack_Enable_IMM30_14 : 24|2@1+ (1,0) [0|3] ""  IMM
 SG_ M2I_Byrack_ReVeEnable_IMM30_14 : 26|2@1+ (1,0) [0|3] ""  IMM
 SG_ Reserved_14 : 28|4@1+ (1,0) [0|15] ""  IMM
 SG_ M2I_Byrack_IsPostTm_IMM30_14 : 32|8@1+ (0.01,0) [0|2.55] "s"  IMM
 SG_ M2I_Byrack_SysABStTm_IMM30_14 : 40|16@1+ (0.01,0) [0|655.35] "s"  IMM
 SG_ Reserved_14 : 56|8@1+ (1,0) [0|255] ""  IMM

BO_ 2332114591 M2I_Byrack_SUMDATA30__15: 8 MBMU
 SG_ CRC_M2I_Byrack_IMM30_15 : 0|8@1+ (1,0) [0|255] ""  IMM
 SG_ M2I_Byrack_HVS_IMM30_15 : 8|16@1+ (0.1,0) [0|6553.5] "v"  IMM
 SG_ M2I_Byrack_Enable_IMM30_15 : 24|2@1+ (1,0) [0|3] ""  IMM
 SG_ M2I_Byrack_ReVeEnable_IMM30_15 : 26|2@1+ (1,0) [0|3] ""  IMM
 SG_ Reserved_15 : 28|4@1+ (1,0) [0|15] ""  IMM
 SG_ M2I_Byrack_IsPostTm_IMM30_15 : 32|8@1+ (0.01,0) [0|2.55] "s"  IMM
 SG_ M2I_Byrack_SysABStTm_IMM30_15 : 40|16@1+ (0.01,0) [0|655.35] "s"  IMM
 SG_ Reserved_15 : 56|8@1+ (1,0) [0|255] ""  IMM

BO_ 2332114592 M2I_Byrack_SUMDATA30__16: 8 MBMU
 SG_ CRC_M2I_Byrack_IMM30_16 : 0|8@1+ (1,0) [0|255] ""  IMM
 SG_ M2I_Byrack_HVS_IMM30_16 : 8|16@1+ (0.1,0) [0|6553.5] "v"  IMM
 SG_ M2I_Byrack_Enable_IMM30_16 : 24|2@1+ (1,0) [0|3] ""  IMM
 SG_ M2I_Byrack_ReVeEnable_IMM30_16 : 26|2@1+ (1,0) [0|3] ""  IMM
 SG_ Reserved_16 : 28|4@1+ (1,0) [0|15] ""  IMM
 SG_ M2I_Byrack_IsPostTm_IMM30_16 : 32|8@1+ (0.01,0) [0|2.55] "s"  IMM
 SG_ M2I_Byrack_SysABStTm_IMM30_16 : 40|16@1+ (0.01,0) [0|655.35] "s"  IMM
 SG_ Reserved_16 : 56|8@1+ (1,0) [0|255] ""  IMM

BO_ 2332114593 M2I_Byrack_SUMDATA30__17: 8 MBMU
 SG_ CRC_M2I_Byrack_IMM30_17 : 0|8@1+ (1,0) [0|255] ""  IMM
 SG_ M2I_Byrack_HVS_IMM30_17 : 8|16@1+ (0.1,0) [0|6553.5] "v"  IMM
 SG_ M2I_Byrack_Enable_IMM30_17 : 24|2@1+ (1,0) [0|3] ""  IMM
 SG_ M2I_Byrack_ReVeEnable_IMM30_17 : 26|2@1+ (1,0) [0|3] ""  IMM
 SG_ Reserved_17 : 28|4@1+ (1,0) [0|15] ""  IMM
 SG_ M2I_Byrack_IsPostTm_IMM30_17 : 32|8@1+ (0.01,0) [0|2.55] "s"  IMM
 SG_ M2I_Byrack_SysABStTm_IMM30_17 : 40|16@1+ (0.01,0) [0|655.35] "s"  IMM
 SG_ Reserved_17 : 56|8@1+ (1,0) [0|255] ""  IMM

BO_ 2332114594 M2I_Byrack_SUMDATA30__18: 8 MBMU
 SG_ CRC_M2I_Byrack_IMM30_18 : 0|8@1+ (1,0) [0|255] ""  IMM
 SG_ M2I_Byrack_HVS_IMM30_18 : 8|16@1+ (0.1,0) [0|6553.5] "v"  IMM
 SG_ M2I_Byrack_Enable_IMM30_18 : 24|2@1+ (1,0) [0|3] ""  IMM
 SG_ M2I_Byrack_ReVeEnable_IMM30_18 : 26|2@1+ (1,0) [0|3] ""  IMM
 SG_ Reserved_18 : 28|4@1+ (1,0) [0|15] ""  IMM
 SG_ M2I_Byrack_IsPostTm_IMM30_18 : 32|8@1+ (0.01,0) [0|2.55] "s"  IMM
 SG_ M2I_Byrack_SysABStTm_IMM30_18 : 40|16@1+ (0.01,0) [0|655.35] "s"  IMM
 SG_ Reserved_18 : 56|8@1+ (1,0) [0|255] ""  IMM

BO_ 2332114595 M2I_Byrack_SUMDATA30__19: 8 MBMU
 SG_ CRC_M2I_Byrack_IMM30_19 : 0|8@1+ (1,0) [0|255] ""  IMM
 SG_ M2I_Byrack_HVS_IMM30_19 : 8|16@1+ (0.1,0) [0|6553.5] "v"  IMM
 SG_ M2I_Byrack_Enable_IMM30_19 : 24|2@1+ (1,0) [0|3] ""  IMM
 SG_ M2I_Byrack_ReVeEnable_IMM30_19 : 26|2@1+ (1,0) [0|3] ""  IMM
 SG_ Reserved_19 : 28|4@1+ (1,0) [0|15] ""  IMM
 SG_ M2I_Byrack_IsPostTm_IMM30_19 : 32|8@1+ (0.01,0) [0|2.55] "s"  IMM
 SG_ M2I_Byrack_SysABStTm_IMM30_19 : 40|16@1+ (0.01,0) [0|655.35] "s"  IMM
 SG_ Reserved_19 : 56|8@1+ (1,0) [0|255] ""  IMM

BO_ 2332114596 M2I_Byrack_SUMDATA30__20: 8 MBMU
 SG_ CRC_M2I_Byrack_IMM30_20 : 0|8@1+ (1,0) [0|255] ""  IMM
 SG_ M2I_Byrack_HVS_IMM30_20 : 8|16@1+ (0.1,0) [0|6553.5] "v"  IMM
 SG_ M2I_Byrack_Enable_IMM30_20 : 24|2@1+ (1,0) [0|3] ""  IMM
 SG_ M2I_Byrack_ReVeEnable_IMM30_20 : 26|2@1+ (1,0) [0|3] ""  IMM
 SG_ Reserved_20 : 28|4@1+ (1,0) [0|15] ""  IMM
 SG_ M2I_Byrack_IsPostTm_IMM30_20 : 32|8@1+ (0.01,0) [0|2.55] "s"  IMM
 SG_ M2I_Byrack_SysABStTm_IMM30_20 : 40|16@1+ (0.01,0) [0|655.35] "s"  IMM
 SG_ Reserved_20 : 56|8@1+ (1,0) [0|255] ""  IMM

BO_ 2332114597 M2I_Byrack_SUMDATA30__21: 8 MBMU
 SG_ CRC_M2I_Byrack_IMM30_21 : 0|8@1+ (1,0) [0|255] ""  IMM
 SG_ M2I_Byrack_HVS_IMM30_21 : 8|16@1+ (0.1,0) [0|6553.5] "v"  IMM
 SG_ M2I_Byrack_Enable_IMM30_21 : 24|2@1+ (1,0) [0|3] ""  IMM
 SG_ M2I_Byrack_ReVeEnable_IMM30_21 : 26|2@1+ (1,0) [0|3] ""  IMM
 SG_ Reserved_21 : 28|4@1+ (1,0) [0|15] ""  IMM
 SG_ M2I_Byrack_IsPostTm_IMM30_21 : 32|8@1+ (0.01,0) [0|2.55] "s"  IMM
 SG_ M2I_Byrack_SysABStTm_IMM30_21 : 40|16@1+ (0.01,0) [0|655.35] "s"  IMM
 SG_ Reserved_21 : 56|8@1+ (1,0) [0|255] ""  IMM

BO_ 2332114598 M2I_Byrack_SUMDATA30__22: 8 MBMU
 SG_ CRC_M2I_Byrack_IMM30_22 : 0|8@1+ (1,0) [0|255] ""  IMM
 SG_ M2I_Byrack_HVS_IMM30_22 : 8|16@1+ (0.1,0) [0|6553.5] "v"  IMM
 SG_ M2I_Byrack_Enable_IMM30_22 : 24|2@1+ (1,0) [0|3] ""  IMM
 SG_ M2I_Byrack_ReVeEnable_IMM30_22 : 26|2@1+ (1,0) [0|3] ""  IMM
 SG_ Reserved_22 : 28|4@1+ (1,0) [0|15] ""  IMM
 SG_ M2I_Byrack_IsPostTm_IMM30_22 : 32|8@1+ (0.01,0) [0|2.55] "s"  IMM
 SG_ M2I_Byrack_SysABStTm_IMM30_22 : 40|16@1+ (0.01,0) [0|655.35] "s"  IMM
 SG_ Reserved_22 : 56|8@1+ (1,0) [0|255] ""  IMM

BO_ 2332114599 M2I_Byrack_SUMDATA30__23: 8 MBMU
 SG_ CRC_M2I_Byrack_IMM30_23 : 0|8@1+ (1,0) [0|255] ""  IMM
 SG_ M2I_Byrack_HVS_IMM30_23 : 8|16@1+ (0.1,0) [0|6553.5] "v"  IMM
 SG_ M2I_Byrack_Enable_IMM30_23 : 24|2@1+ (1,0) [0|3] ""  IMM
 SG_ M2I_Byrack_ReVeEnable_IMM30_23 : 26|2@1+ (1,0) [0|3] ""  IMM
 SG_ Reserved_23 : 28|4@1+ (1,0) [0|15] ""  IMM
 SG_ M2I_Byrack_IsPostTm_IMM30_23 : 32|8@1+ (0.01,0) [0|2.55] "s"  IMM
 SG_ M2I_Byrack_SysABStTm_IMM30_23 : 40|16@1+ (0.01,0) [0|655.35] "s"  IMM
 SG_ Reserved_23 : 56|8@1+ (1,0) [0|255] ""  IMM

BO_ 2332114600 M2I_Byrack_SUMDATA30__24: 8 MBMU
 SG_ CRC_M2I_Byrack_IMM30_24 : 0|8@1+ (1,0) [0|255] ""  IMM
 SG_ M2I_Byrack_HVS_IMM30_24 : 8|16@1+ (0.1,0) [0|6553.5] "v"  IMM
 SG_ M2I_Byrack_Enable_IMM30_24 : 24|2@1+ (1,0) [0|3] ""  IMM
 SG_ M2I_Byrack_ReVeEnable_IMM30_24 : 26|2@1+ (1,0) [0|3] ""  IMM
 SG_ Reserved_24 : 28|4@1+ (1,0) [0|15] ""  IMM
 SG_ M2I_Byrack_IsPostTm_IMM30_24 : 32|8@1+ (0.01,0) [0|2.55] "s"  IMM
 SG_ M2I_Byrack_SysABStTm_IMM30_24 : 40|16@1+ (0.01,0) [0|655.35] "s"  IMM
 SG_ Reserved_24 : 56|8@1+ (1,0) [0|255] ""  IMM

BO_ 2332114601 M2I_Byrack_SUMDATA30__25: 8 MBMU
 SG_ CRC_M2I_Byrack_IMM30_25 : 0|8@1+ (1,0) [0|255] ""  IMM
 SG_ M2I_Byrack_HVS_IMM30_25 : 8|16@1+ (0.1,0) [0|6553.5] "v"  IMM
 SG_ M2I_Byrack_Enable_IMM30_25 : 24|2@1+ (1,0) [0|3] ""  IMM
 SG_ M2I_Byrack_ReVeEnable_IMM30_25 : 26|2@1+ (1,0) [0|3] ""  IMM
 SG_ Reserved_25 : 28|4@1+ (1,0) [0|15] ""  IMM
 SG_ M2I_Byrack_IsPostTm_IMM30_25 : 32|8@1+ (0.01,0) [0|2.55] "s"  IMM
 SG_ M2I_Byrack_SysABStTm_IMM30_25 : 40|16@1+ (0.01,0) [0|655.35] "s"  IMM
 SG_ Reserved_25 : 56|8@1+ (1,0) [0|255] ""  IMM

BO_ 2332114602 M2I_Byrack_SUMDATA30__26: 8 MBMU
 SG_ CRC_M2I_Byrack_IMM30_26 : 0|8@1+ (1,0) [0|255] ""  IMM
 SG_ M2I_Byrack_HVS_IMM30_26 : 8|16@1+ (0.1,0) [0|6553.5] "v"  IMM
 SG_ M2I_Byrack_Enable_IMM30_26 : 24|2@1+ (1,0) [0|3] ""  IMM
 SG_ M2I_Byrack_ReVeEnable_IMM30_26 : 26|2@1+ (1,0) [0|3] ""  IMM
 SG_ Reserved_26 : 28|4@1+ (1,0) [0|15] ""  IMM
 SG_ M2I_Byrack_IsPostTm_IMM30_26 : 32|8@1+ (0.01,0) [0|2.55] "s"  IMM
 SG_ M2I_Byrack_SysABStTm_IMM30_26 : 40|16@1+ (0.01,0) [0|655.35] "s"  IMM
 SG_ Reserved_26 : 56|8@1+ (1,0) [0|255] ""  IMM

BO_ 2332114603 M2I_Byrack_SUMDATA30__27: 8 MBMU
 SG_ CRC_M2I_Byrack_IMM30_27 : 0|8@1+ (1,0) [0|255] ""  IMM
 SG_ M2I_Byrack_HVS_IMM30_27 : 8|16@1+ (0.1,0) [0|6553.5] "v"  IMM
 SG_ M2I_Byrack_Enable_IMM30_27 : 24|2@1+ (1,0) [0|3] ""  IMM
 SG_ M2I_Byrack_ReVeEnable_IMM30_27 : 26|2@1+ (1,0) [0|3] ""  IMM
 SG_ Reserved_27 : 28|4@1+ (1,0) [0|15] ""  IMM
 SG_ M2I_Byrack_IsPostTm_IMM30_27 : 32|8@1+ (0.01,0) [0|2.55] "s"  IMM
 SG_ M2I_Byrack_SysABStTm_IMM30_27 : 40|16@1+ (0.01,0) [0|655.35] "s"  IMM
 SG_ Reserved_27 : 56|8@1+ (1,0) [0|255] ""  IMM

BO_ 2332114604 M2I_Byrack_SUMDATA30__28: 8 MBMU
 SG_ CRC_M2I_Byrack_IMM30_28 : 0|8@1+ (1,0) [0|255] ""  IMM
 SG_ M2I_Byrack_HVS_IMM30_28 : 8|16@1+ (0.1,0) [0|6553.5] "v"  IMM
 SG_ M2I_Byrack_Enable_IMM30_28 : 24|2@1+ (1,0) [0|3] ""  IMM
 SG_ M2I_Byrack_ReVeEnable_IMM30_28 : 26|2@1+ (1,0) [0|3] ""  IMM
 SG_ Reserved_28 : 28|4@1+ (1,0) [0|15] ""  IMM
 SG_ M2I_Byrack_IsPostTm_IMM30_28 : 32|8@1+ (0.01,0) [0|2.55] "s"  IMM
 SG_ M2I_Byrack_SysABStTm_IMM30_28 : 40|16@1+ (0.01,0) [0|655.35] "s"  IMM
 SG_ Reserved_28 : 56|8@1+ (1,0) [0|255] ""  IMM

BO_ 2332114605 M2I_Byrack_SUMDATA30__29: 8 MBMU
 SG_ CRC_M2I_Byrack_IMM30_29 : 0|8@1+ (1,0) [0|255] ""  IMM
 SG_ M2I_Byrack_HVS_IMM30_29 : 8|16@1+ (0.1,0) [0|6553.5] "v"  IMM
 SG_ M2I_Byrack_Enable_IMM30_29 : 24|2@1+ (1,0) [0|3] ""  IMM
 SG_ M2I_Byrack_ReVeEnable_IMM30_29 : 26|2@1+ (1,0) [0|3] ""  IMM
 SG_ Reserved_29 : 28|4@1+ (1,0) [0|15] ""  IMM
 SG_ M2I_Byrack_IsPostTm_IMM30_29 : 32|8@1+ (0.01,0) [0|2.55] "s"  IMM
 SG_ M2I_Byrack_SysABStTm_IMM30_29 : 40|16@1+ (0.01,0) [0|655.35] "s"  IMM
 SG_ Reserved_29 : 56|8@1+ (1,0) [0|255] ""  IMM

BO_ 2332114606 M2I_Byrack_SUMDATA30__30: 8 MBMU
 SG_ CRC_M2I_Byrack_IMM30_30 : 0|8@1+ (1,0) [0|255] ""  IMM
 SG_ M2I_Byrack_HVS_IMM30_30 : 8|16@1+ (0.1,0) [0|6553.5] "v"  IMM
 SG_ M2I_Byrack_Enable_IMM30_30 : 24|2@1+ (1,0) [0|3] ""  IMM
 SG_ M2I_Byrack_ReVeEnable_IMM30_30 : 26|2@1+ (1,0) [0|3] ""  IMM
 SG_ Reserved_30 : 28|4@1+ (1,0) [0|15] ""  IMM
 SG_ M2I_Byrack_IsPostTm_IMM30_30 : 32|8@1+ (0.01,0) [0|2.55] "s"  IMM
 SG_ M2I_Byrack_SysABStTm_IMM30_30 : 40|16@1+ (0.01,0) [0|655.35] "s"  IMM
 SG_ Reserved_30 : 56|8@1+ (1,0) [0|255] ""  IMM

BO_ 2332114607 M2I_Byrack_SUMDATA30__31: 8 MBMU
 SG_ CRC_M2I_Byrack_IMM30_31 : 0|8@1+ (1,0) [0|255] ""  IMM
 SG_ M2I_Byrack_HVS_IMM30_31 : 8|16@1+ (0.1,0) [0|6553.5] "v"  IMM
 SG_ M2I_Byrack_Enable_IMM30_31 : 24|2@1+ (1,0) [0|3] ""  IMM
 SG_ M2I_Byrack_ReVeEnable_IMM30_31 : 26|2@1+ (1,0) [0|3] ""  IMM
 SG_ Reserved_31 : 28|4@1+ (1,0) [0|15] ""  IMM
 SG_ M2I_Byrack_IsPostTm_IMM30_31 : 32|8@1+ (0.01,0) [0|2.55] "s"  IMM
 SG_ M2I_Byrack_SysABStTm_IMM30_31 : 40|16@1+ (0.01,0) [0|655.35] "s"  IMM
 SG_ Reserved_31 : 56|8@1+ (1,0) [0|255] ""  IMM

BO_ 2332114833 M2I_Byrack_SUMDATA31__01: 8 MBMU
 SG_ CRC_M2I_Byrack_IMM31_01 : 0|8@1+ (1,0) [0|255] ""  IMM
 SG_ M2I_Byrack_HVS_IMM31_01 : 8|16@1+ (0.1,0) [0|6553.5] "v"  IMM
 SG_ M2I_Byrack_Enable_IMM31_01 : 24|2@1+ (1,0) [0|3] ""  IMM
 SG_ M2I_Byrack_ReVeEnable_IMM31_01 : 26|2@1+ (1,0) [0|3] ""  IMM
 SG_ Reserved_01 : 28|4@1+ (1,0) [0|15] ""  IMM
 SG_ M2I_Byrack_IsPostTm_IMM31_01 : 32|8@1+ (0.01,0) [0|2.55] "s"  IMM
 SG_ M2I_Byrack_SysABStTm_IMM31_01 : 40|16@1+ (0.01,0) [0|655.35] "s"  IMM
 SG_ Reserved_01 : 56|8@1+ (1,0) [0|255] ""  IMM

BO_ 2332114834 M2I_Byrack_SUMDATA31__02: 8 MBMU
 SG_ CRC_M2I_Byrack_IMM31_02 : 0|8@1+ (1,0) [0|255] ""  IMM
 SG_ M2I_Byrack_HVS_IMM31_02 : 8|16@1+ (0.1,0) [0|6553.5] "v"  IMM
 SG_ M2I_Byrack_Enable_IMM31_02 : 24|2@1+ (1,0) [0|3] ""  IMM
 SG_ M2I_Byrack_ReVeEnable_IMM31_02 : 26|2@1+ (1,0) [0|3] ""  IMM
 SG_ Reserved_02 : 28|4@1+ (1,0) [0|15] ""  IMM
 SG_ M2I_Byrack_IsPostTm_IMM31_02 : 32|8@1+ (0.01,0) [0|2.55] "s"  IMM
 SG_ M2I_Byrack_SysABStTm_IMM31_02 : 40|16@1+ (0.01,0) [0|655.35] "s"  IMM
 SG_ Reserved_02 : 56|8@1+ (1,0) [0|255] ""  IMM

BO_ 2332114835 M2I_Byrack_SUMDATA31__03: 8 MBMU
 SG_ CRC_M2I_Byrack_IMM31_03 : 0|8@1+ (1,0) [0|255] ""  IMM
 SG_ M2I_Byrack_HVS_IMM31_03 : 8|16@1+ (0.1,0) [0|6553.5] "v"  IMM
 SG_ M2I_Byrack_Enable_IMM31_03 : 24|2@1+ (1,0) [0|3] ""  IMM
 SG_ M2I_Byrack_ReVeEnable_IMM31_03 : 26|2@1+ (1,0) [0|3] ""  IMM
 SG_ Reserved_03 : 28|4@1+ (1,0) [0|15] ""  IMM
 SG_ M2I_Byrack_IsPostTm_IMM31_03 : 32|8@1+ (0.01,0) [0|2.55] "s"  IMM
 SG_ M2I_Byrack_SysABStTm_IMM31_03 : 40|16@1+ (0.01,0) [0|655.35] "s"  IMM
 SG_ Reserved_03 : 56|8@1+ (1,0) [0|255] ""  IMM

BO_ 2332114836 M2I_Byrack_SUMDATA31__04: 8 MBMU
 SG_ CRC_M2I_Byrack_IMM31_04 : 0|8@1+ (1,0) [0|255] ""  IMM
 SG_ M2I_Byrack_HVS_IMM31_04 : 8|16@1+ (0.1,0) [0|6553.5] "v"  IMM
 SG_ M2I_Byrack_Enable_IMM31_04 : 24|2@1+ (1,0) [0|3] ""  IMM
 SG_ M2I_Byrack_ReVeEnable_IMM31_04 : 26|2@1+ (1,0) [0|3] ""  IMM
 SG_ Reserved_04 : 28|4@1+ (1,0) [0|15] ""  IMM
 SG_ M2I_Byrack_IsPostTm_IMM31_04 : 32|8@1+ (0.01,0) [0|2.55] "s"  IMM
 SG_ M2I_Byrack_SysABStTm_IMM31_04 : 40|16@1+ (0.01,0) [0|655.35] "s"  IMM
 SG_ Reserved_04 : 56|8@1+ (1,0) [0|255] ""  IMM

BO_ 2332114837 M2I_Byrack_SUMDATA31__05: 8 MBMU
 SG_ CRC_M2I_Byrack_IMM31_05 : 0|8@1+ (1,0) [0|255] ""  IMM
 SG_ M2I_Byrack_HVS_IMM31_05 : 8|16@1+ (0.1,0) [0|6553.5] "v"  IMM
 SG_ M2I_Byrack_Enable_IMM31_05 : 24|2@1+ (1,0) [0|3] ""  IMM
 SG_ M2I_Byrack_ReVeEnable_IMM31_05 : 26|2@1+ (1,0) [0|3] ""  IMM
 SG_ Reserved_05 : 28|4@1+ (1,0) [0|15] ""  IMM
 SG_ M2I_Byrack_IsPostTm_IMM31_05 : 32|8@1+ (0.01,0) [0|2.55] "s"  IMM
 SG_ M2I_Byrack_SysABStTm_IMM31_05 : 40|16@1+ (0.01,0) [0|655.35] "s"  IMM
 SG_ Reserved_05 : 56|8@1+ (1,0) [0|255] ""  IMM

BO_ 2332114838 M2I_Byrack_SUMDATA31__06: 8 MBMU
 SG_ CRC_M2I_Byrack_IMM31_06 : 0|8@1+ (1,0) [0|255] ""  IMM
 SG_ M2I_Byrack_HVS_IMM31_06 : 8|16@1+ (0.1,0) [0|6553.5] "v"  IMM
 SG_ M2I_Byrack_Enable_IMM31_06 : 24|2@1+ (1,0) [0|3] ""  IMM
 SG_ M2I_Byrack_ReVeEnable_IMM31_06 : 26|2@1+ (1,0) [0|3] ""  IMM
 SG_ Reserved_06 : 28|4@1+ (1,0) [0|15] ""  IMM
 SG_ M2I_Byrack_IsPostTm_IMM31_06 : 32|8@1+ (0.01,0) [0|2.55] "s"  IMM
 SG_ M2I_Byrack_SysABStTm_IMM31_06 : 40|16@1+ (0.01,0) [0|655.35] "s"  IMM
 SG_ Reserved_06 : 56|8@1+ (1,0) [0|255] ""  IMM

BO_ 2332114839 M2I_Byrack_SUMDATA31__07: 8 MBMU
 SG_ CRC_M2I_Byrack_IMM31_07 : 0|8@1+ (1,0) [0|255] ""  IMM
 SG_ M2I_Byrack_HVS_IMM31_07 : 8|16@1+ (0.1,0) [0|6553.5] "v"  IMM
 SG_ M2I_Byrack_Enable_IMM31_07 : 24|2@1+ (1,0) [0|3] ""  IMM
 SG_ M2I_Byrack_ReVeEnable_IMM31_07 : 26|2@1+ (1,0) [0|3] ""  IMM
 SG_ Reserved_07 : 28|4@1+ (1,0) [0|15] ""  IMM
 SG_ M2I_Byrack_IsPostTm_IMM31_07 : 32|8@1+ (0.01,0) [0|2.55] "s"  IMM
 SG_ M2I_Byrack_SysABStTm_IMM31_07 : 40|16@1+ (0.01,0) [0|655.35] "s"  IMM
 SG_ Reserved_07 : 56|8@1+ (1,0) [0|255] ""  IMM

BO_ 2332114840 M2I_Byrack_SUMDATA31__08: 8 MBMU
 SG_ CRC_M2I_Byrack_IMM31_08 : 0|8@1+ (1,0) [0|255] ""  IMM
 SG_ M2I_Byrack_HVS_IMM31_08 : 8|16@1+ (0.1,0) [0|6553.5] "v"  IMM
 SG_ M2I_Byrack_Enable_IMM31_08 : 24|2@1+ (1,0) [0|3] ""  IMM
 SG_ M2I_Byrack_ReVeEnable_IMM31_08 : 26|2@1+ (1,0) [0|3] ""  IMM
 SG_ Reserved_08 : 28|4@1+ (1,0) [0|15] ""  IMM
 SG_ M2I_Byrack_IsPostTm_IMM31_08 : 32|8@1+ (0.01,0) [0|2.55] "s"  IMM
 SG_ M2I_Byrack_SysABStTm_IMM31_08 : 40|16@1+ (0.01,0) [0|655.35] "s"  IMM
 SG_ Reserved_08 : 56|8@1+ (1,0) [0|255] ""  IMM

BO_ 2332114841 M2I_Byrack_SUMDATA31__09: 8 MBMU
 SG_ CRC_M2I_Byrack_IMM31_09 : 0|8@1+ (1,0) [0|255] ""  IMM
 SG_ M2I_Byrack_HVS_IMM31_09 : 8|16@1+ (0.1,0) [0|6553.5] "v"  IMM
 SG_ M2I_Byrack_Enable_IMM31_09 : 24|2@1+ (1,0) [0|3] ""  IMM
 SG_ M2I_Byrack_ReVeEnable_IMM31_09 : 26|2@1+ (1,0) [0|3] ""  IMM
 SG_ Reserved_09 : 28|4@1+ (1,0) [0|15] ""  IMM
 SG_ M2I_Byrack_IsPostTm_IMM31_09 : 32|8@1+ (0.01,0) [0|2.55] "s"  IMM
 SG_ M2I_Byrack_SysABStTm_IMM31_09 : 40|16@1+ (0.01,0) [0|655.35] "s"  IMM
 SG_ Reserved_09 : 56|8@1+ (1,0) [0|255] ""  IMM

BO_ 2332114842 M2I_Byrack_SUMDATA31__10: 8 MBMU
 SG_ CRC_M2I_Byrack_IMM31_10 : 0|8@1+ (1,0) [0|255] ""  IMM
 SG_ M2I_Byrack_HVS_IMM31_10 : 8|16@1+ (0.1,0) [0|6553.5] "v"  IMM
 SG_ M2I_Byrack_Enable_IMM31_10 : 24|2@1+ (1,0) [0|3] ""  IMM
 SG_ M2I_Byrack_ReVeEnable_IMM31_10 : 26|2@1+ (1,0) [0|3] ""  IMM
 SG_ Reserved_10 : 28|4@1+ (1,0) [0|15] ""  IMM
 SG_ M2I_Byrack_IsPostTm_IMM31_10 : 32|8@1+ (0.01,0) [0|2.55] "s"  IMM
 SG_ M2I_Byrack_SysABStTm_IMM31_10 : 40|16@1+ (0.01,0) [0|655.35] "s"  IMM
 SG_ Reserved_10 : 56|8@1+ (1,0) [0|255] ""  IMM

BO_ 2332114843 M2I_Byrack_SUMDATA31__11: 8 MBMU
 SG_ CRC_M2I_Byrack_IMM31_11 : 0|8@1+ (1,0) [0|255] ""  IMM
 SG_ M2I_Byrack_HVS_IMM31_11 : 8|16@1+ (0.1,0) [0|6553.5] "v"  IMM
 SG_ M2I_Byrack_Enable_IMM31_11 : 24|2@1+ (1,0) [0|3] ""  IMM
 SG_ M2I_Byrack_ReVeEnable_IMM31_11 : 26|2@1+ (1,0) [0|3] ""  IMM
 SG_ Reserved_11 : 28|4@1+ (1,0) [0|15] ""  IMM
 SG_ M2I_Byrack_IsPostTm_IMM31_11 : 32|8@1+ (0.01,0) [0|2.55] "s"  IMM
 SG_ M2I_Byrack_SysABStTm_IMM31_11 : 40|16@1+ (0.01,0) [0|655.35] "s"  IMM
 SG_ Reserved_11 : 56|8@1+ (1,0) [0|255] ""  IMM

BO_ 2332114844 M2I_Byrack_SUMDATA31__12: 8 MBMU
 SG_ CRC_M2I_Byrack_IMM31_12 : 0|8@1+ (1,0) [0|255] ""  IMM
 SG_ M2I_Byrack_HVS_IMM31_12 : 8|16@1+ (0.1,0) [0|6553.5] "v"  IMM
 SG_ M2I_Byrack_Enable_IMM31_12 : 24|2@1+ (1,0) [0|3] ""  IMM
 SG_ M2I_Byrack_ReVeEnable_IMM31_12 : 26|2@1+ (1,0) [0|3] ""  IMM
 SG_ Reserved_12 : 28|4@1+ (1,0) [0|15] ""  IMM
 SG_ M2I_Byrack_IsPostTm_IMM31_12 : 32|8@1+ (0.01,0) [0|2.55] "s"  IMM
 SG_ M2I_Byrack_SysABStTm_IMM31_12 : 40|16@1+ (0.01,0) [0|655.35] "s"  IMM
 SG_ Reserved_12 : 56|8@1+ (1,0) [0|255] ""  IMM

BO_ 2332114845 M2I_Byrack_SUMDATA31__13: 8 MBMU
 SG_ CRC_M2I_Byrack_IMM31_13 : 0|8@1+ (1,0) [0|255] ""  IMM
 SG_ M2I_Byrack_HVS_IMM31_13 : 8|16@1+ (0.1,0) [0|6553.5] "v"  IMM
 SG_ M2I_Byrack_Enable_IMM31_13 : 24|2@1+ (1,0) [0|3] ""  IMM
 SG_ M2I_Byrack_ReVeEnable_IMM31_13 : 26|2@1+ (1,0) [0|3] ""  IMM
 SG_ Reserved_13 : 28|4@1+ (1,0) [0|15] ""  IMM
 SG_ M2I_Byrack_IsPostTm_IMM31_13 : 32|8@1+ (0.01,0) [0|2.55] "s"  IMM
 SG_ M2I_Byrack_SysABStTm_IMM31_13 : 40|16@1+ (0.01,0) [0|655.35] "s"  IMM
 SG_ Reserved_13 : 56|8@1+ (1,0) [0|255] ""  IMM

BO_ 2332114846 M2I_Byrack_SUMDATA31__14: 8 MBMU
 SG_ CRC_M2I_Byrack_IMM31_14 : 0|8@1+ (1,0) [0|255] ""  IMM
 SG_ M2I_Byrack_HVS_IMM31_14 : 8|16@1+ (0.1,0) [0|6553.5] "v"  IMM
 SG_ M2I_Byrack_Enable_IMM31_14 : 24|2@1+ (1,0) [0|3] ""  IMM
 SG_ M2I_Byrack_ReVeEnable_IMM31_14 : 26|2@1+ (1,0) [0|3] ""  IMM
 SG_ Reserved_14 : 28|4@1+ (1,0) [0|15] ""  IMM
 SG_ M2I_Byrack_IsPostTm_IMM31_14 : 32|8@1+ (0.01,0) [0|2.55] "s"  IMM
 SG_ M2I_Byrack_SysABStTm_IMM31_14 : 40|16@1+ (0.01,0) [0|655.35] "s"  IMM
 SG_ Reserved_14 : 56|8@1+ (1,0) [0|255] ""  IMM

BO_ 2332114847 M2I_Byrack_SUMDATA31__15: 8 MBMU
 SG_ CRC_M2I_Byrack_IMM31_15 : 0|8@1+ (1,0) [0|255] ""  IMM
 SG_ M2I_Byrack_HVS_IMM31_15 : 8|16@1+ (0.1,0) [0|6553.5] "v"  IMM
 SG_ M2I_Byrack_Enable_IMM31_15 : 24|2@1+ (1,0) [0|3] ""  IMM
 SG_ M2I_Byrack_ReVeEnable_IMM31_15 : 26|2@1+ (1,0) [0|3] ""  IMM
 SG_ Reserved_15 : 28|4@1+ (1,0) [0|15] ""  IMM
 SG_ M2I_Byrack_IsPostTm_IMM31_15 : 32|8@1+ (0.01,0) [0|2.55] "s"  IMM
 SG_ M2I_Byrack_SysABStTm_IMM31_15 : 40|16@1+ (0.01,0) [0|655.35] "s"  IMM
 SG_ Reserved_15 : 56|8@1+ (1,0) [0|255] ""  IMM

BO_ 2332114848 M2I_Byrack_SUMDATA31__16: 8 MBMU
 SG_ CRC_M2I_Byrack_IMM31_16 : 0|8@1+ (1,0) [0|255] ""  IMM
 SG_ M2I_Byrack_HVS_IMM31_16 : 8|16@1+ (0.1,0) [0|6553.5] "v"  IMM
 SG_ M2I_Byrack_Enable_IMM31_16 : 24|2@1+ (1,0) [0|3] ""  IMM
 SG_ M2I_Byrack_ReVeEnable_IMM31_16 : 26|2@1+ (1,0) [0|3] ""  IMM
 SG_ Reserved_16 : 28|4@1+ (1,0) [0|15] ""  IMM
 SG_ M2I_Byrack_IsPostTm_IMM31_16 : 32|8@1+ (0.01,0) [0|2.55] "s"  IMM
 SG_ M2I_Byrack_SysABStTm_IMM31_16 : 40|16@1+ (0.01,0) [0|655.35] "s"  IMM
 SG_ Reserved_16 : 56|8@1+ (1,0) [0|255] ""  IMM

BO_ 2332114849 M2I_Byrack_SUMDATA31__17: 8 MBMU
 SG_ CRC_M2I_Byrack_IMM31_17 : 0|8@1+ (1,0) [0|255] ""  IMM
 SG_ M2I_Byrack_HVS_IMM31_17 : 8|16@1+ (0.1,0) [0|6553.5] "v"  IMM
 SG_ M2I_Byrack_Enable_IMM31_17 : 24|2@1+ (1,0) [0|3] ""  IMM
 SG_ M2I_Byrack_ReVeEnable_IMM31_17 : 26|2@1+ (1,0) [0|3] ""  IMM
 SG_ Reserved_17 : 28|4@1+ (1,0) [0|15] ""  IMM
 SG_ M2I_Byrack_IsPostTm_IMM31_17 : 32|8@1+ (0.01,0) [0|2.55] "s"  IMM
 SG_ M2I_Byrack_SysABStTm_IMM31_17 : 40|16@1+ (0.01,0) [0|655.35] "s"  IMM
 SG_ Reserved_17 : 56|8@1+ (1,0) [0|255] ""  IMM

BO_ 2332114850 M2I_Byrack_SUMDATA31__18: 8 MBMU
 SG_ CRC_M2I_Byrack_IMM31_18 : 0|8@1+ (1,0) [0|255] ""  IMM
 SG_ M2I_Byrack_HVS_IMM31_18 : 8|16@1+ (0.1,0) [0|6553.5] "v"  IMM
 SG_ M2I_Byrack_Enable_IMM31_18 : 24|2@1+ (1,0) [0|3] ""  IMM
 SG_ M2I_Byrack_ReVeEnable_IMM31_18 : 26|2@1+ (1,0) [0|3] ""  IMM
 SG_ Reserved_18 : 28|4@1+ (1,0) [0|15] ""  IMM
 SG_ M2I_Byrack_IsPostTm_IMM31_18 : 32|8@1+ (0.01,0) [0|2.55] "s"  IMM
 SG_ M2I_Byrack_SysABStTm_IMM31_18 : 40|16@1+ (0.01,0) [0|655.35] "s"  IMM
 SG_ Reserved_18 : 56|8@1+ (1,0) [0|255] ""  IMM

BO_ 2332114851 M2I_Byrack_SUMDATA31__19: 8 MBMU
 SG_ CRC_M2I_Byrack_IMM31_19 : 0|8@1+ (1,0) [0|255] ""  IMM
 SG_ M2I_Byrack_HVS_IMM31_19 : 8|16@1+ (0.1,0) [0|6553.5] "v"  IMM
 SG_ M2I_Byrack_Enable_IMM31_19 : 24|2@1+ (1,0) [0|3] ""  IMM
 SG_ M2I_Byrack_ReVeEnable_IMM31_19 : 26|2@1+ (1,0) [0|3] ""  IMM
 SG_ Reserved_19 : 28|4@1+ (1,0) [0|15] ""  IMM
 SG_ M2I_Byrack_IsPostTm_IMM31_19 : 32|8@1+ (0.01,0) [0|2.55] "s"  IMM
 SG_ M2I_Byrack_SysABStTm_IMM31_19 : 40|16@1+ (0.01,0) [0|655.35] "s"  IMM
 SG_ Reserved_19 : 56|8@1+ (1,0) [0|255] ""  IMM

BO_ 2332114852 M2I_Byrack_SUMDATA31__20: 8 MBMU
 SG_ CRC_M2I_Byrack_IMM31_20 : 0|8@1+ (1,0) [0|255] ""  IMM
 SG_ M2I_Byrack_HVS_IMM31_20 : 8|16@1+ (0.1,0) [0|6553.5] "v"  IMM
 SG_ M2I_Byrack_Enable_IMM31_20 : 24|2@1+ (1,0) [0|3] ""  IMM
 SG_ M2I_Byrack_ReVeEnable_IMM31_20 : 26|2@1+ (1,0) [0|3] ""  IMM
 SG_ Reserved_20 : 28|4@1+ (1,0) [0|15] ""  IMM
 SG_ M2I_Byrack_IsPostTm_IMM31_20 : 32|8@1+ (0.01,0) [0|2.55] "s"  IMM
 SG_ M2I_Byrack_SysABStTm_IMM31_20 : 40|16@1+ (0.01,0) [0|655.35] "s"  IMM
 SG_ Reserved_20 : 56|8@1+ (1,0) [0|255] ""  IMM

BO_ 2332114853 M2I_Byrack_SUMDATA31__21: 8 MBMU
 SG_ CRC_M2I_Byrack_IMM31_21 : 0|8@1+ (1,0) [0|255] ""  IMM
 SG_ M2I_Byrack_HVS_IMM31_21 : 8|16@1+ (0.1,0) [0|6553.5] "v"  IMM
 SG_ M2I_Byrack_Enable_IMM31_21 : 24|2@1+ (1,0) [0|3] ""  IMM
 SG_ M2I_Byrack_ReVeEnable_IMM31_21 : 26|2@1+ (1,0) [0|3] ""  IMM
 SG_ Reserved_21 : 28|4@1+ (1,0) [0|15] ""  IMM
 SG_ M2I_Byrack_IsPostTm_IMM31_21 : 32|8@1+ (0.01,0) [0|2.55] "s"  IMM
 SG_ M2I_Byrack_SysABStTm_IMM31_21 : 40|16@1+ (0.01,0) [0|655.35] "s"  IMM
 SG_ Reserved_21 : 56|8@1+ (1,0) [0|255] ""  IMM

BO_ 2332114854 M2I_Byrack_SUMDATA31__22: 8 MBMU
 SG_ CRC_M2I_Byrack_IMM31_22 : 0|8@1+ (1,0) [0|255] ""  IMM
 SG_ M2I_Byrack_HVS_IMM31_22 : 8|16@1+ (0.1,0) [0|6553.5] "v"  IMM
 SG_ M2I_Byrack_Enable_IMM31_22 : 24|2@1+ (1,0) [0|3] ""  IMM
 SG_ M2I_Byrack_ReVeEnable_IMM31_22 : 26|2@1+ (1,0) [0|3] ""  IMM
 SG_ Reserved_22 : 28|4@1+ (1,0) [0|15] ""  IMM
 SG_ M2I_Byrack_IsPostTm_IMM31_22 : 32|8@1+ (0.01,0) [0|2.55] "s"  IMM
 SG_ M2I_Byrack_SysABStTm_IMM31_22 : 40|16@1+ (0.01,0) [0|655.35] "s"  IMM
 SG_ Reserved_22 : 56|8@1+ (1,0) [0|255] ""  IMM

BO_ 2332114855 M2I_Byrack_SUMDATA31__23: 8 MBMU
 SG_ CRC_M2I_Byrack_IMM31_23 : 0|8@1+ (1,0) [0|255] ""  IMM
 SG_ M2I_Byrack_HVS_IMM31_23 : 8|16@1+ (0.1,0) [0|6553.5] "v"  IMM
 SG_ M2I_Byrack_Enable_IMM31_23 : 24|2@1+ (1,0) [0|3] ""  IMM
 SG_ M2I_Byrack_ReVeEnable_IMM31_23 : 26|2@1+ (1,0) [0|3] ""  IMM
 SG_ Reserved_23 : 28|4@1+ (1,0) [0|15] ""  IMM
 SG_ M2I_Byrack_IsPostTm_IMM31_23 : 32|8@1+ (0.01,0) [0|2.55] "s"  IMM
 SG_ M2I_Byrack_SysABStTm_IMM31_23 : 40|16@1+ (0.01,0) [0|655.35] "s"  IMM
 SG_ Reserved_23 : 56|8@1+ (1,0) [0|255] ""  IMM

BO_ 2332114856 M2I_Byrack_SUMDATA31__24: 8 MBMU
 SG_ CRC_M2I_Byrack_IMM31_24 : 0|8@1+ (1,0) [0|255] ""  IMM
 SG_ M2I_Byrack_HVS_IMM31_24 : 8|16@1+ (0.1,0) [0|6553.5] "v"  IMM
 SG_ M2I_Byrack_Enable_IMM31_24 : 24|2@1+ (1,0) [0|3] ""  IMM
 SG_ M2I_Byrack_ReVeEnable_IMM31_24 : 26|2@1+ (1,0) [0|3] ""  IMM
 SG_ Reserved_24 : 28|4@1+ (1,0) [0|15] ""  IMM
 SG_ M2I_Byrack_IsPostTm_IMM31_24 : 32|8@1+ (0.01,0) [0|2.55] "s"  IMM
 SG_ M2I_Byrack_SysABStTm_IMM31_24 : 40|16@1+ (0.01,0) [0|655.35] "s"  IMM
 SG_ Reserved_24 : 56|8@1+ (1,0) [0|255] ""  IMM

BO_ 2332114857 M2I_Byrack_SUMDATA31__25: 8 MBMU
 SG_ CRC_M2I_Byrack_IMM31_25 : 0|8@1+ (1,0) [0|255] ""  IMM
 SG_ M2I_Byrack_HVS_IMM31_25 : 8|16@1+ (0.1,0) [0|6553.5] "v"  IMM
 SG_ M2I_Byrack_Enable_IMM31_25 : 24|2@1+ (1,0) [0|3] ""  IMM
 SG_ M2I_Byrack_ReVeEnable_IMM31_25 : 26|2@1+ (1,0) [0|3] ""  IMM
 SG_ Reserved_25 : 28|4@1+ (1,0) [0|15] ""  IMM
 SG_ M2I_Byrack_IsPostTm_IMM31_25 : 32|8@1+ (0.01,0) [0|2.55] "s"  IMM
 SG_ M2I_Byrack_SysABStTm_IMM31_25 : 40|16@1+ (0.01,0) [0|655.35] "s"  IMM
 SG_ Reserved_25 : 56|8@1+ (1,0) [0|255] ""  IMM

BO_ 2332114858 M2I_Byrack_SUMDATA31__26: 8 MBMU
 SG_ CRC_M2I_Byrack_IMM31_26 : 0|8@1+ (1,0) [0|255] ""  IMM
 SG_ M2I_Byrack_HVS_IMM31_26 : 8|16@1+ (0.1,0) [0|6553.5] "v"  IMM
 SG_ M2I_Byrack_Enable_IMM31_26 : 24|2@1+ (1,0) [0|3] ""  IMM
 SG_ M2I_Byrack_ReVeEnable_IMM31_26 : 26|2@1+ (1,0) [0|3] ""  IMM
 SG_ Reserved_26 : 28|4@1+ (1,0) [0|15] ""  IMM
 SG_ M2I_Byrack_IsPostTm_IMM31_26 : 32|8@1+ (0.01,0) [0|2.55] "s"  IMM
 SG_ M2I_Byrack_SysABStTm_IMM31_26 : 40|16@1+ (0.01,0) [0|655.35] "s"  IMM
 SG_ Reserved_26 : 56|8@1+ (1,0) [0|255] ""  IMM

BO_ 2332114859 M2I_Byrack_SUMDATA31__27: 8 MBMU
 SG_ CRC_M2I_Byrack_IMM31_27 : 0|8@1+ (1,0) [0|255] ""  IMM
 SG_ M2I_Byrack_HVS_IMM31_27 : 8|16@1+ (0.1,0) [0|6553.5] "v"  IMM
 SG_ M2I_Byrack_Enable_IMM31_27 : 24|2@1+ (1,0) [0|3] ""  IMM
 SG_ M2I_Byrack_ReVeEnable_IMM31_27 : 26|2@1+ (1,0) [0|3] ""  IMM
 SG_ Reserved_27 : 28|4@1+ (1,0) [0|15] ""  IMM
 SG_ M2I_Byrack_IsPostTm_IMM31_27 : 32|8@1+ (0.01,0) [0|2.55] "s"  IMM
 SG_ M2I_Byrack_SysABStTm_IMM31_27 : 40|16@1+ (0.01,0) [0|655.35] "s"  IMM
 SG_ Reserved_27 : 56|8@1+ (1,0) [0|255] ""  IMM

BO_ 2332114860 M2I_Byrack_SUMDATA31__28: 8 MBMU
 SG_ CRC_M2I_Byrack_IMM31_28 : 0|8@1+ (1,0) [0|255] ""  IMM
 SG_ M2I_Byrack_HVS_IMM31_28 : 8|16@1+ (0.1,0) [0|6553.5] "v"  IMM
 SG_ M2I_Byrack_Enable_IMM31_28 : 24|2@1+ (1,0) [0|3] ""  IMM
 SG_ M2I_Byrack_ReVeEnable_IMM31_28 : 26|2@1+ (1,0) [0|3] ""  IMM
 SG_ Reserved_28 : 28|4@1+ (1,0) [0|15] ""  IMM
 SG_ M2I_Byrack_IsPostTm_IMM31_28 : 32|8@1+ (0.01,0) [0|2.55] "s"  IMM
 SG_ M2I_Byrack_SysABStTm_IMM31_28 : 40|16@1+ (0.01,0) [0|655.35] "s"  IMM
 SG_ Reserved_28 : 56|8@1+ (1,0) [0|255] ""  IMM

BO_ 2332114861 M2I_Byrack_SUMDATA31__29: 8 MBMU
 SG_ CRC_M2I_Byrack_IMM31_29 : 0|8@1+ (1,0) [0|255] ""  IMM
 SG_ M2I_Byrack_HVS_IMM31_29 : 8|16@1+ (0.1,0) [0|6553.5] "v"  IMM
 SG_ M2I_Byrack_Enable_IMM31_29 : 24|2@1+ (1,0) [0|3] ""  IMM
 SG_ M2I_Byrack_ReVeEnable_IMM31_29 : 26|2@1+ (1,0) [0|3] ""  IMM
 SG_ Reserved_29 : 28|4@1+ (1,0) [0|15] ""  IMM
 SG_ M2I_Byrack_IsPostTm_IMM31_29 : 32|8@1+ (0.01,0) [0|2.55] "s"  IMM
 SG_ M2I_Byrack_SysABStTm_IMM31_29 : 40|16@1+ (0.01,0) [0|655.35] "s"  IMM
 SG_ Reserved_29 : 56|8@1+ (1,0) [0|255] ""  IMM

BO_ 2332114862 M2I_Byrack_SUMDATA31__30: 8 MBMU
 SG_ CRC_M2I_Byrack_IMM31_30 : 0|8@1+ (1,0) [0|255] ""  IMM
 SG_ M2I_Byrack_HVS_IMM31_30 : 8|16@1+ (0.1,0) [0|6553.5] "v"  IMM
 SG_ M2I_Byrack_Enable_IMM31_30 : 24|2@1+ (1,0) [0|3] ""  IMM
 SG_ M2I_Byrack_ReVeEnable_IMM31_30 : 26|2@1+ (1,0) [0|3] ""  IMM
 SG_ Reserved_30 : 28|4@1+ (1,0) [0|15] ""  IMM
 SG_ M2I_Byrack_IsPostTm_IMM31_30 : 32|8@1+ (0.01,0) [0|2.55] "s"  IMM
 SG_ M2I_Byrack_SysABStTm_IMM31_30 : 40|16@1+ (0.01,0) [0|655.35] "s"  IMM
 SG_ Reserved_30 : 56|8@1+ (1,0) [0|255] ""  IMM

BO_ 2332114863 M2I_Byrack_SUMDATA31__31: 8 MBMU
 SG_ CRC_M2I_Byrack_IMM31_31 : 0|8@1+ (1,0) [0|255] ""  IMM
 SG_ M2I_Byrack_HVS_IMM31_31 : 8|16@1+ (0.1,0) [0|6553.5] "v"  IMM
 SG_ M2I_Byrack_Enable_IMM31_31 : 24|2@1+ (1,0) [0|3] ""  IMM
 SG_ M2I_Byrack_ReVeEnable_IMM31_31 : 26|2@1+ (1,0) [0|3] ""  IMM
 SG_ Reserved_31 : 28|4@1+ (1,0) [0|15] ""  IMM
 SG_ M2I_Byrack_IsPostTm_IMM31_31 : 32|8@1+ (0.01,0) [0|2.55] "s"  IMM
 SG_ M2I_Byrack_SysABStTm_IMM31_31 : 40|16@1+ (0.01,0) [0|655.35] "s"  IMM
 SG_ Reserved_31 : 56|8@1+ (1,0) [0|255] ""  IMM

BO_ 2332946065 M2P_SUMDATA13__01: 8 MBMU
 SG_ Reserved_01 : 0|64@1+ (1,0) [0|1.84467440737096E+019] ""  PC

BO_ 2332946066 M2P_SUMDATA13__02: 8 MBMU
 SG_ Reserved_02 : 0|64@1+ (1,0) [0|1.84467440737096E+019] ""  PC

BO_ 2332946067 M2P_SUMDATA13__03: 8 MBMU
 SG_ Reserved_03 : 0|64@1+ (1,0) [0|1.84467440737096E+019] ""  PC

BO_ 2332946068 M2P_SUMDATA13__04: 8 MBMU
 SG_ Reserved_04 : 0|64@1+ (1,0) [0|1.84467440737096E+019] ""  PC

BO_ 2332946069 M2P_SUMDATA13__05: 8 MBMU
 SG_ Reserved_05 : 0|64@1+ (1,0) [0|1.84467440737096E+019] ""  PC

BO_ 2332946070 M2P_SUMDATA13__06: 8 MBMU
 SG_ Reserved_06 : 0|64@1+ (1,0) [0|1.84467440737096E+019] ""  PC

BO_ 2332946071 M2P_SUMDATA13__07: 8 MBMU
 SG_ Reserved_07 : 0|64@1+ (1,0) [0|1.84467440737096E+019] ""  PC

BO_ 2332946072 M2P_SUMDATA13__08: 8 MBMU
 SG_ Reserved_08 : 0|64@1+ (1,0) [0|1.84467440737096E+019] ""  PC

BO_ 2332946073 M2P_SUMDATA13__09: 8 MBMU
 SG_ Reserved_09 : 0|64@1+ (1,0) [0|1.84467440737096E+019] ""  PC

BO_ 2332946074 M2P_SUMDATA13__10: 8 MBMU
 SG_ Reserved_10 : 0|64@1+ (1,0) [0|1.84467440737096E+019] ""  PC

BO_ 2332946075 M2P_SUMDATA13__11: 8 MBMU
 SG_ Reserved_11 : 0|64@1+ (1,0) [0|1.84467440737096E+019] ""  PC

BO_ 2332946076 M2P_SUMDATA13__12: 8 MBMU
 SG_ Reserved_12 : 0|64@1+ (1,0) [0|1.84467440737096E+019] ""  PC

BO_ 2332946077 M2P_SUMDATA13__13: 8 MBMU
 SG_ Reserved_13 : 0|64@1+ (1,0) [0|1.84467440737096E+019] ""  PC

BO_ 2332946078 M2P_SUMDATA13__14: 8 MBMU
 SG_ Reserved_14 : 0|64@1+ (1,0) [0|1.84467440737096E+019] ""  PC

BO_ 2332946079 M2P_SUMDATA13__15: 8 MBMU
 SG_ Reserved_15 : 0|64@1+ (1,0) [0|1.84467440737096E+019] ""  PC

BO_ 2332946080 M2P_SUMDATA13__16: 8 MBMU
 SG_ Reserved_16 : 0|64@1+ (1,0) [0|1.84467440737096E+019] ""  PC

BO_ 2332946081 M2P_SUMDATA13__17: 8 MBMU
 SG_ Reserved_17 : 0|64@1+ (1,0) [0|1.84467440737096E+019] ""  PC

BO_ 2332946082 M2P_SUMDATA13__18: 8 MBMU
 SG_ Reserved_18 : 0|64@1+ (1,0) [0|1.84467440737096E+019] ""  PC

BO_ 2332946083 M2P_SUMDATA13__19: 8 MBMU
 SG_ Reserved_19 : 0|64@1+ (1,0) [0|1.84467440737096E+019] ""  PC

BO_ 2332946084 M2P_SUMDATA13__20: 8 MBMU
 SG_ Reserved_20 : 0|64@1+ (1,0) [0|1.84467440737096E+019] ""  PC

BO_ 2332946085 M2P_SUMDATA13__21: 8 MBMU
 SG_ Reserved_21 : 0|64@1+ (1,0) [0|1.84467440737096E+019] ""  PC

BO_ 2332946086 M2P_SUMDATA13__22: 8 MBMU
 SG_ Reserved_22 : 0|64@1+ (1,0) [0|1.84467440737096E+019] ""  PC

BO_ 2332946087 M2P_SUMDATA13__23: 8 MBMU
 SG_ Reserved_23 : 0|64@1+ (1,0) [0|1.84467440737096E+019] ""  PC

BO_ 2332946088 M2P_SUMDATA13__24: 8 MBMU
 SG_ Reserved_24 : 0|64@1+ (1,0) [0|1.84467440737096E+019] ""  PC

BO_ 2332946089 M2P_SUMDATA13__25: 8 MBMU
 SG_ Reserved_25 : 0|64@1+ (1,0) [0|1.84467440737096E+019] ""  PC

BO_ 2332946090 M2P_SUMDATA13__26: 8 MBMU
 SG_ Reserved_26 : 0|64@1+ (1,0) [0|1.84467440737096E+019] ""  PC

BO_ 2332946091 M2P_SUMDATA13__27: 8 MBMU
 SG_ Reserved_27 : 0|64@1+ (1,0) [0|1.84467440737096E+019] ""  PC

BO_ 2332946092 M2P_SUMDATA13__28: 8 MBMU
 SG_ Reserved_28 : 0|64@1+ (1,0) [0|1.84467440737096E+019] ""  PC

BO_ 2332946093 M2P_SUMDATA13__29: 8 MBMU
 SG_ Reserved_29 : 0|64@1+ (1,0) [0|1.84467440737096E+019] ""  PC

BO_ 2332946094 M2P_SUMDATA13__30: 8 MBMU
 SG_ Reserved_30 : 0|64@1+ (1,0) [0|1.84467440737096E+019] ""  PC

BO_ 2332946095 M2P_SUMDATA13__31: 8 MBMU
 SG_ Reserved_31 : 0|64@1+ (1,0) [0|1.84467440737096E+019] ""  PC

BO_ 2333077137 M2P_SUMDATA14__01: 8 MBMU
 SG_ Reserved_01 : 0|64@1+ (1,0) [0|1.84467440737096E+019] ""  PC

BO_ 2333077138 M2P_SUMDATA14__02: 8 MBMU
 SG_ Reserved_02 : 0|64@1+ (1,0) [0|1.84467440737096E+019] ""  PC

BO_ 2333077139 M2P_SUMDATA14__03: 8 MBMU
 SG_ Reserved_03 : 0|64@1+ (1,0) [0|1.84467440737096E+019] ""  PC

BO_ 2333077140 M2P_SUMDATA14__04: 8 MBMU
 SG_ Reserved_04 : 0|64@1+ (1,0) [0|1.84467440737096E+019] ""  PC

BO_ 2333077141 M2P_SUMDATA14__05: 8 MBMU
 SG_ Reserved_05 : 0|64@1+ (1,0) [0|1.84467440737096E+019] ""  PC

BO_ 2333077142 M2P_SUMDATA14__06: 8 MBMU
 SG_ Reserved_06 : 0|64@1+ (1,0) [0|1.84467440737096E+019] ""  PC

BO_ 2333077143 M2P_SUMDATA14__07: 8 MBMU
 SG_ Reserved_07 : 0|64@1+ (1,0) [0|1.84467440737096E+019] ""  PC

BO_ 2333077144 M2P_SUMDATA14__08: 8 MBMU
 SG_ Reserved_08 : 0|64@1+ (1,0) [0|1.84467440737096E+019] ""  PC

BO_ 2333077145 M2P_SUMDATA14__09: 8 MBMU
 SG_ Reserved_09 : 0|64@1+ (1,0) [0|1.84467440737096E+019] ""  PC

BO_ 2333077146 M2P_SUMDATA14__10: 8 MBMU
 SG_ Reserved_10 : 0|64@1+ (1,0) [0|1.84467440737096E+019] ""  PC

BO_ 2333077147 M2P_SUMDATA14__11: 8 MBMU
 SG_ Reserved_11 : 0|64@1+ (1,0) [0|1.84467440737096E+019] ""  PC

CM_ SG_ 2332113579 CRC_M2I_Byrack_IMM26_27 "CRC校验_IMM26";
CM_ SG_ 2332113579 M2I_Byrack_HVS_IMM26_27 "绝缘测量电压_IMM26";
CM_ SG_ 2332113579 M2I_Byrack_Enable_IMM26_27 "绝缘采样使能位_IMM26";
CM_ SG_ 2332113579 M2I_Byrack_ReVeEnable_IMM26_27 "读取软件版本使能位_IMM26";
CM_ SG_ 2332113579 Reserved_27 "预留预留";
CM_ SG_ 2332113579 M2I_Byrack_IsPostTm_IMM26_27 "绝缘采样时间_IMM26";
CM_ SG_ 2332113579 M2I_Byrack_SysABStTm_IMM26_27 "电压稳定时间_IMM26";
CM_ SG_ 2332113580 CRC_M2I_Byrack_IMM26_28 "CRC校验_IMM26";
CM_ SG_ 2332113580 M2I_Byrack_HVS_IMM26_28 "绝缘测量电压_IMM26";
CM_ SG_ 2332113580 M2I_Byrack_Enable_IMM26_28 "绝缘采样使能位_IMM26";
CM_ SG_ 2332113580 M2I_Byrack_ReVeEnable_IMM26_28 "读取软件版本使能位_IMM26";
CM_ SG_ 2332113580 Reserved_28 "预留预留";
CM_ SG_ 2332113580 M2I_Byrack_IsPostTm_IMM26_28 "绝缘采样时间_IMM26";
CM_ SG_ 2332113580 M2I_Byrack_SysABStTm_IMM26_28 "电压稳定时间_IMM26";
CM_ SG_ 2332113581 CRC_M2I_Byrack_IMM26_29 "CRC校验_IMM26";
CM_ SG_ 2332113581 M2I_Byrack_HVS_IMM26_29 "绝缘测量电压_IMM26";
CM_ SG_ 2332113581 M2I_Byrack_Enable_IMM26_29 "绝缘采样使能位_IMM26";
CM_ SG_ 2332113581 M2I_Byrack_ReVeEnable_IMM26_29 "读取软件版本使能位_IMM26";
CM_ SG_ 2332113581 Reserved_29 "预留预留";
CM_ SG_ 2332113581 M2I_Byrack_IsPostTm_IMM26_29 "绝缘采样时间_IMM26";
CM_ SG_ 2332113581 M2I_Byrack_SysABStTm_IMM26_29 "电压稳定时间_IMM26";
CM_ SG_ 2332113582 CRC_M2I_Byrack_IMM26_30 "CRC校验_IMM26";
CM_ SG_ 2332113582 M2I_Byrack_HVS_IMM26_30 "绝缘测量电压_IMM26";
CM_ SG_ 2332113582 M2I_Byrack_Enable_IMM26_30 "绝缘采样使能位_IMM26";
CM_ SG_ 2332113582 M2I_Byrack_ReVeEnable_IMM26_30 "读取软件版本使能位_IMM26";
CM_ SG_ 2332113582 Reserved_30 "预留预留";
CM_ SG_ 2332113582 M2I_Byrack_IsPostTm_IMM26_30 "绝缘采样时间_IMM26";
CM_ SG_ 2332113582 M2I_Byrack_SysABStTm_IMM26_30 "电压稳定时间_IMM26";
CM_ SG_ 2332113583 CRC_M2I_Byrack_IMM26_31 "CRC校验_IMM26";
CM_ SG_ 2332113583 M2I_Byrack_HVS_IMM26_31 "绝缘测量电压_IMM26";
CM_ SG_ 2332113583 M2I_Byrack_Enable_IMM26_31 "绝缘采样使能位_IMM26";
CM_ SG_ 2332113583 M2I_Byrack_ReVeEnable_IMM26_31 "读取软件版本使能位_IMM26";
CM_ SG_ 2332113583 Reserved_31 "预留预留";
CM_ SG_ 2332113583 M2I_Byrack_IsPostTm_IMM26_31 "绝缘采样时间_IMM26";
CM_ SG_ 2332113583 M2I_Byrack_SysABStTm_IMM26_31 "电压稳定时间_IMM26";
CM_ SG_ 2332113809 CRC_M2I_Byrack_IMM27_01 "CRC校验_IMM27";
CM_ SG_ 2332113809 M2I_Byrack_HVS_IMM27_01 "绝缘测量电压_IMM27";
CM_ SG_ 2332113809 M2I_Byrack_Enable_IMM27_01 "绝缘采样使能位_IMM27";
CM_ SG_ 2332113809 M2I_Byrack_ReVeEnable_IMM27_01 "读取软件版本使能位_IMM27";
CM_ SG_ 2332113809 Reserved_01 "预留预留";
CM_ SG_ 2332113809 M2I_Byrack_IsPostTm_IMM27_01 "绝缘采样时间_IMM27";
CM_ SG_ 2332113809 M2I_Byrack_SysABStTm_IMM27_01 "电压稳定时间_IMM27";
CM_ SG_ 2332113810 CRC_M2I_Byrack_IMM27_02 "CRC校验_IMM27";
CM_ SG_ 2332113810 M2I_Byrack_HVS_IMM27_02 "绝缘测量电压_IMM27";
CM_ SG_ 2332113810 M2I_Byrack_Enable_IMM27_02 "绝缘采样使能位_IMM27";
CM_ SG_ 2332113810 M2I_Byrack_ReVeEnable_IMM27_02 "读取软件版本使能位_IMM27";
CM_ SG_ 2332113810 Reserved_02 "预留预留";
CM_ SG_ 2332113810 M2I_Byrack_IsPostTm_IMM27_02 "绝缘采样时间_IMM27";
CM_ SG_ 2332113810 M2I_Byrack_SysABStTm_IMM27_02 "电压稳定时间_IMM27";
CM_ SG_ 2332113811 CRC_M2I_Byrack_IMM27_03 "CRC校验_IMM27";
CM_ SG_ 2332113811 M2I_Byrack_HVS_IMM27_03 "绝缘测量电压_IMM27";
CM_ SG_ 2332113811 M2I_Byrack_Enable_IMM27_03 "绝缘采样使能位_IMM27";
CM_ SG_ 2332113811 M2I_Byrack_ReVeEnable_IMM27_03 "读取软件版本使能位_IMM27";
CM_ SG_ 2332113811 Reserved_03 "预留预留";
CM_ SG_ 2332113811 M2I_Byrack_IsPostTm_IMM27_03 "绝缘采样时间_IMM27";
CM_ SG_ 2332113811 M2I_Byrack_SysABStTm_IMM27_03 "电压稳定时间_IMM27";
CM_ SG_ 2332113812 CRC_M2I_Byrack_IMM27_04 "CRC校验_IMM27";
CM_ SG_ 2332113812 M2I_Byrack_HVS_IMM27_04 "绝缘测量电压_IMM27";
CM_ SG_ 2332113812 M2I_Byrack_Enable_IMM27_04 "绝缘采样使能位_IMM27";
CM_ SG_ 2332113812 M2I_Byrack_ReVeEnable_IMM27_04 "读取软件版本使能位_IMM27";
CM_ SG_ 2332113812 Reserved_04 "预留预留";
CM_ SG_ 2332113812 M2I_Byrack_IsPostTm_IMM27_04 "绝缘采样时间_IMM27";
CM_ SG_ 2332113812 M2I_Byrack_SysABStTm_IMM27_04 "电压稳定时间_IMM27";
CM_ SG_ 2332113813 CRC_M2I_Byrack_IMM27_05 "CRC校验_IMM27";
CM_ SG_ 2332113813 M2I_Byrack_HVS_IMM27_05 "绝缘测量电压_IMM27";
CM_ SG_ 2332113813 M2I_Byrack_Enable_IMM27_05 "绝缘采样使能位_IMM27";
CM_ SG_ 2332113813 M2I_Byrack_ReVeEnable_IMM27_05 "读取软件版本使能位_IMM27";
CM_ SG_ 2332113813 Reserved_05 "预留预留";
CM_ SG_ 2332113813 M2I_Byrack_IsPostTm_IMM27_05 "绝缘采样时间_IMM27";
CM_ SG_ 2332113813 M2I_Byrack_SysABStTm_IMM27_05 "电压稳定时间_IMM27";
CM_ SG_ 2332113814 CRC_M2I_Byrack_IMM27_06 "CRC校验_IMM27";
CM_ SG_ 2332113814 M2I_Byrack_HVS_IMM27_06 "绝缘测量电压_IMM27";
CM_ SG_ 2332113814 M2I_Byrack_Enable_IMM27_06 "绝缘采样使能位_IMM27";
CM_ SG_ 2332113814 M2I_Byrack_ReVeEnable_IMM27_06 "读取软件版本使能位_IMM27";
CM_ SG_ 2332113814 Reserved_06 "预留预留";
CM_ SG_ 2332113814 M2I_Byrack_IsPostTm_IMM27_06 "绝缘采样时间_IMM27";
CM_ SG_ 2332113814 M2I_Byrack_SysABStTm_IMM27_06 "电压稳定时间_IMM27";
CM_ SG_ 2332113815 CRC_M2I_Byrack_IMM27_07 "CRC校验_IMM27";
CM_ SG_ 2332113815 M2I_Byrack_HVS_IMM27_07 "绝缘测量电压_IMM27";
CM_ SG_ 2332113815 M2I_Byrack_Enable_IMM27_07 "绝缘采样使能位_IMM27";
CM_ SG_ 2332113815 M2I_Byrack_ReVeEnable_IMM27_07 "读取软件版本使能位_IMM27";
CM_ SG_ 2332113815 Reserved_07 "预留预留";
CM_ SG_ 2332113815 M2I_Byrack_IsPostTm_IMM27_07 "绝缘采样时间_IMM27";
CM_ SG_ 2332113815 M2I_Byrack_SysABStTm_IMM27_07 "电压稳定时间_IMM27";
CM_ SG_ 2332113816 CRC_M2I_Byrack_IMM27_08 "CRC校验_IMM27";
CM_ SG_ 2332113816 M2I_Byrack_HVS_IMM27_08 "绝缘测量电压_IMM27";
CM_ SG_ 2332113816 M2I_Byrack_Enable_IMM27_08 "绝缘采样使能位_IMM27";
CM_ SG_ 2332113816 M2I_Byrack_ReVeEnable_IMM27_08 "读取软件版本使能位_IMM27";
CM_ SG_ 2332113816 Reserved_08 "预留预留";
CM_ SG_ 2332113816 M2I_Byrack_IsPostTm_IMM27_08 "绝缘采样时间_IMM27";
CM_ SG_ 2332113816 M2I_Byrack_SysABStTm_IMM27_08 "电压稳定时间_IMM27";
CM_ SG_ 2332113817 CRC_M2I_Byrack_IMM27_09 "CRC校验_IMM27";
CM_ SG_ 2332113817 M2I_Byrack_HVS_IMM27_09 "绝缘测量电压_IMM27";
CM_ SG_ 2332113817 M2I_Byrack_Enable_IMM27_09 "绝缘采样使能位_IMM27";
CM_ SG_ 2332113817 M2I_Byrack_ReVeEnable_IMM27_09 "读取软件版本使能位_IMM27";
CM_ SG_ 2332113817 Reserved_09 "预留预留";
CM_ SG_ 2332113817 M2I_Byrack_IsPostTm_IMM27_09 "绝缘采样时间_IMM27";
CM_ SG_ 2332113817 M2I_Byrack_SysABStTm_IMM27_09 "电压稳定时间_IMM27";
CM_ SG_ 2332113818 CRC_M2I_Byrack_IMM27_10 "CRC校验_IMM27";
CM_ SG_ 2332113818 M2I_Byrack_HVS_IMM27_10 "绝缘测量电压_IMM27";
CM_ SG_ 2332113818 M2I_Byrack_Enable_IMM27_10 "绝缘采样使能位_IMM27";
CM_ SG_ 2332113818 M2I_Byrack_ReVeEnable_IMM27_10 "读取软件版本使能位_IMM27";
CM_ SG_ 2332113818 Reserved_10 "预留预留";
CM_ SG_ 2332113818 M2I_Byrack_IsPostTm_IMM27_10 "绝缘采样时间_IMM27";
CM_ SG_ 2332113818 M2I_Byrack_SysABStTm_IMM27_10 "电压稳定时间_IMM27";
CM_ SG_ 2332113819 CRC_M2I_Byrack_IMM27_11 "CRC校验_IMM27";
CM_ SG_ 2332113819 M2I_Byrack_HVS_IMM27_11 "绝缘测量电压_IMM27";
CM_ SG_ 2332113819 M2I_Byrack_Enable_IMM27_11 "绝缘采样使能位_IMM27";
CM_ SG_ 2332113819 M2I_Byrack_ReVeEnable_IMM27_11 "读取软件版本使能位_IMM27";
CM_ SG_ 2332113819 Reserved_11 "预留预留";
CM_ SG_ 2332113819 M2I_Byrack_IsPostTm_IMM27_11 "绝缘采样时间_IMM27";
CM_ SG_ 2332113819 M2I_Byrack_SysABStTm_IMM27_11 "电压稳定时间_IMM27";
CM_ SG_ 2332113820 CRC_M2I_Byrack_IMM27_12 "CRC校验_IMM27";
CM_ SG_ 2332113820 M2I_Byrack_HVS_IMM27_12 "绝缘测量电压_IMM27";
CM_ SG_ 2332113820 M2I_Byrack_Enable_IMM27_12 "绝缘采样使能位_IMM27";
CM_ SG_ 2332113820 M2I_Byrack_ReVeEnable_IMM27_12 "读取软件版本使能位_IMM27";
CM_ SG_ 2332113820 Reserved_12 "预留预留";
CM_ SG_ 2332113820 M2I_Byrack_IsPostTm_IMM27_12 "绝缘采样时间_IMM27";
CM_ SG_ 2332113820 M2I_Byrack_SysABStTm_IMM27_12 "电压稳定时间_IMM27";
CM_ SG_ 2332113821 CRC_M2I_Byrack_IMM27_13 "CRC校验_IMM27";
CM_ SG_ 2332113821 M2I_Byrack_HVS_IMM27_13 "绝缘测量电压_IMM27";
CM_ SG_ 2332113821 M2I_Byrack_Enable_IMM27_13 "绝缘采样使能位_IMM27";
CM_ SG_ 2332113821 M2I_Byrack_ReVeEnable_IMM27_13 "读取软件版本使能位_IMM27";
CM_ SG_ 2332113821 Reserved_13 "预留预留";
CM_ SG_ 2332113821 M2I_Byrack_IsPostTm_IMM27_13 "绝缘采样时间_IMM27";
CM_ SG_ 2332113821 M2I_Byrack_SysABStTm_IMM27_13 "电压稳定时间_IMM27";
CM_ SG_ 2332113822 CRC_M2I_Byrack_IMM27_14 "CRC校验_IMM27";
CM_ SG_ 2332113822 M2I_Byrack_HVS_IMM27_14 "绝缘测量电压_IMM27";
CM_ SG_ 2332113822 M2I_Byrack_Enable_IMM27_14 "绝缘采样使能位_IMM27";
CM_ SG_ 2332113822 M2I_Byrack_ReVeEnable_IMM27_14 "读取软件版本使能位_IMM27";
CM_ SG_ 2332113822 Reserved_14 "预留预留";
CM_ SG_ 2332113822 M2I_Byrack_IsPostTm_IMM27_14 "绝缘采样时间_IMM27";
CM_ SG_ 2332113822 M2I_Byrack_SysABStTm_IMM27_14 "电压稳定时间_IMM27";
CM_ SG_ 2332113823 CRC_M2I_Byrack_IMM27_15 "CRC校验_IMM27";
CM_ SG_ 2332113823 M2I_Byrack_HVS_IMM27_15 "绝缘测量电压_IMM27";
CM_ SG_ 2332113823 M2I_Byrack_Enable_IMM27_15 "绝缘采样使能位_IMM27";
CM_ SG_ 2332113823 M2I_Byrack_ReVeEnable_IMM27_15 "读取软件版本使能位_IMM27";
CM_ SG_ 2332113823 Reserved_15 "预留预留";
CM_ SG_ 2332113823 M2I_Byrack_IsPostTm_IMM27_15 "绝缘采样时间_IMM27";
CM_ SG_ 2332113823 M2I_Byrack_SysABStTm_IMM27_15 "电压稳定时间_IMM27";
CM_ SG_ 2332113824 CRC_M2I_Byrack_IMM27_16 "CRC校验_IMM27";
CM_ SG_ 2332113824 M2I_Byrack_HVS_IMM27_16 "绝缘测量电压_IMM27";
CM_ SG_ 2332113824 M2I_Byrack_Enable_IMM27_16 "绝缘采样使能位_IMM27";
CM_ SG_ 2332113824 M2I_Byrack_ReVeEnable_IMM27_16 "读取软件版本使能位_IMM27";
CM_ SG_ 2332113824 Reserved_16 "预留预留";
CM_ SG_ 2332113824 M2I_Byrack_IsPostTm_IMM27_16 "绝缘采样时间_IMM27";
CM_ SG_ 2332113824 M2I_Byrack_SysABStTm_IMM27_16 "电压稳定时间_IMM27";
CM_ SG_ 2332113825 CRC_M2I_Byrack_IMM27_17 "CRC校验_IMM27";
CM_ SG_ 2332113825 M2I_Byrack_HVS_IMM27_17 "绝缘测量电压_IMM27";
CM_ SG_ 2332113825 M2I_Byrack_Enable_IMM27_17 "绝缘采样使能位_IMM27";
CM_ SG_ 2332113825 M2I_Byrack_ReVeEnable_IMM27_17 "读取软件版本使能位_IMM27";
CM_ SG_ 2332113825 Reserved_17 "预留预留";
CM_ SG_ 2332113825 M2I_Byrack_IsPostTm_IMM27_17 "绝缘采样时间_IMM27";
CM_ SG_ 2332113825 M2I_Byrack_SysABStTm_IMM27_17 "电压稳定时间_IMM27";
CM_ SG_ 2332113826 CRC_M2I_Byrack_IMM27_18 "CRC校验_IMM27";
CM_ SG_ 2332113826 M2I_Byrack_HVS_IMM27_18 "绝缘测量电压_IMM27";
CM_ SG_ 2332113826 M2I_Byrack_Enable_IMM27_18 "绝缘采样使能位_IMM27";
CM_ SG_ 2332113826 M2I_Byrack_ReVeEnable_IMM27_18 "读取软件版本使能位_IMM27";
CM_ SG_ 2332113826 Reserved_18 "预留预留";
CM_ SG_ 2332113826 M2I_Byrack_IsPostTm_IMM27_18 "绝缘采样时间_IMM27";
CM_ SG_ 2332113826 M2I_Byrack_SysABStTm_IMM27_18 "电压稳定时间_IMM27";
CM_ SG_ 2332113827 CRC_M2I_Byrack_IMM27_19 "CRC校验_IMM27";
CM_ SG_ 2332113827 M2I_Byrack_HVS_IMM27_19 "绝缘测量电压_IMM27";
CM_ SG_ 2332113827 M2I_Byrack_Enable_IMM27_19 "绝缘采样使能位_IMM27";
CM_ SG_ 2332113827 M2I_Byrack_ReVeEnable_IMM27_19 "读取软件版本使能位_IMM27";
CM_ SG_ 2332113827 Reserved_19 "预留预留";
CM_ SG_ 2332113827 M2I_Byrack_IsPostTm_IMM27_19 "绝缘采样时间_IMM27";
CM_ SG_ 2332113827 M2I_Byrack_SysABStTm_IMM27_19 "电压稳定时间_IMM27";
CM_ SG_ 2332113828 CRC_M2I_Byrack_IMM27_20 "CRC校验_IMM27";
CM_ SG_ 2332113828 M2I_Byrack_HVS_IMM27_20 "绝缘测量电压_IMM27";
CM_ SG_ 2332113828 M2I_Byrack_Enable_IMM27_20 "绝缘采样使能位_IMM27";
CM_ SG_ 2332113828 M2I_Byrack_ReVeEnable_IMM27_20 "读取软件版本使能位_IMM27";
CM_ SG_ 2332113828 Reserved_20 "预留预留";
CM_ SG_ 2332113828 M2I_Byrack_IsPostTm_IMM27_20 "绝缘采样时间_IMM27";
CM_ SG_ 2332113828 M2I_Byrack_SysABStTm_IMM27_20 "电压稳定时间_IMM27";
CM_ SG_ 2332113829 CRC_M2I_Byrack_IMM27_21 "CRC校验_IMM27";
CM_ SG_ 2332113829 M2I_Byrack_HVS_IMM27_21 "绝缘测量电压_IMM27";
CM_ SG_ 2332113829 M2I_Byrack_Enable_IMM27_21 "绝缘采样使能位_IMM27";
CM_ SG_ 2332113829 M2I_Byrack_ReVeEnable_IMM27_21 "读取软件版本使能位_IMM27";
CM_ SG_ 2332113829 Reserved_21 "预留预留";
CM_ SG_ 2332113829 M2I_Byrack_IsPostTm_IMM27_21 "绝缘采样时间_IMM27";
CM_ SG_ 2332113829 M2I_Byrack_SysABStTm_IMM27_21 "电压稳定时间_IMM27";
CM_ SG_ 2332113830 CRC_M2I_Byrack_IMM27_22 "CRC校验_IMM27";
CM_ SG_ 2332113830 M2I_Byrack_HVS_IMM27_22 "绝缘测量电压_IMM27";
CM_ SG_ 2332113830 M2I_Byrack_Enable_IMM27_22 "绝缘采样使能位_IMM27";
CM_ SG_ 2332113830 M2I_Byrack_ReVeEnable_IMM27_22 "读取软件版本使能位_IMM27";
CM_ SG_ 2332113830 Reserved_22 "预留预留";
CM_ SG_ 2332113830 M2I_Byrack_IsPostTm_IMM27_22 "绝缘采样时间_IMM27";
CM_ SG_ 2332113830 M2I_Byrack_SysABStTm_IMM27_22 "电压稳定时间_IMM27";
CM_ SG_ 2332113831 CRC_M2I_Byrack_IMM27_23 "CRC校验_IMM27";
CM_ SG_ 2332113831 M2I_Byrack_HVS_IMM27_23 "绝缘测量电压_IMM27";
CM_ SG_ 2332113831 M2I_Byrack_Enable_IMM27_23 "绝缘采样使能位_IMM27";
CM_ SG_ 2332113831 M2I_Byrack_ReVeEnable_IMM27_23 "读取软件版本使能位_IMM27";
CM_ SG_ 2332113831 Reserved_23 "预留预留";
CM_ SG_ 2332113831 M2I_Byrack_IsPostTm_IMM27_23 "绝缘采样时间_IMM27";
CM_ SG_ 2332113831 M2I_Byrack_SysABStTm_IMM27_23 "电压稳定时间_IMM27";
CM_ SG_ 2332113832 CRC_M2I_Byrack_IMM27_24 "CRC校验_IMM27";
CM_ SG_ 2332113832 M2I_Byrack_HVS_IMM27_24 "绝缘测量电压_IMM27";
CM_ SG_ 2332113832 M2I_Byrack_Enable_IMM27_24 "绝缘采样使能位_IMM27";
CM_ SG_ 2332113832 M2I_Byrack_ReVeEnable_IMM27_24 "读取软件版本使能位_IMM27";
CM_ SG_ 2332113832 Reserved_24 "预留预留";
CM_ SG_ 2332113832 M2I_Byrack_IsPostTm_IMM27_24 "绝缘采样时间_IMM27";
CM_ SG_ 2332113832 M2I_Byrack_SysABStTm_IMM27_24 "电压稳定时间_IMM27";
CM_ SG_ 2332113833 CRC_M2I_Byrack_IMM27_25 "CRC校验_IMM27";
CM_ SG_ 2332113833 M2I_Byrack_HVS_IMM27_25 "绝缘测量电压_IMM27";
CM_ SG_ 2332113833 M2I_Byrack_Enable_IMM27_25 "绝缘采样使能位_IMM27";
CM_ SG_ 2332113833 M2I_Byrack_ReVeEnable_IMM27_25 "读取软件版本使能位_IMM27";
CM_ SG_ 2332113833 Reserved_25 "预留预留";
CM_ SG_ 2332113833 M2I_Byrack_IsPostTm_IMM27_25 "绝缘采样时间_IMM27";
CM_ SG_ 2332113833 M2I_Byrack_SysABStTm_IMM27_25 "电压稳定时间_IMM27";
CM_ SG_ 2332113834 CRC_M2I_Byrack_IMM27_26 "CRC校验_IMM27";
CM_ SG_ 2332113834 M2I_Byrack_HVS_IMM27_26 "绝缘测量电压_IMM27";
CM_ SG_ 2332113834 M2I_Byrack_Enable_IMM27_26 "绝缘采样使能位_IMM27";
CM_ SG_ 2332113834 M2I_Byrack_ReVeEnable_IMM27_26 "读取软件版本使能位_IMM27";
CM_ SG_ 2332113834 Reserved_26 "预留预留";
CM_ SG_ 2332113834 M2I_Byrack_IsPostTm_IMM27_26 "绝缘采样时间_IMM27";
CM_ SG_ 2332113834 M2I_Byrack_SysABStTm_IMM27_26 "电压稳定时间_IMM27";
CM_ SG_ 2332113835 CRC_M2I_Byrack_IMM27_27 "CRC校验_IMM27";
CM_ SG_ 2332113835 M2I_Byrack_HVS_IMM27_27 "绝缘测量电压_IMM27";
CM_ SG_ 2332113835 M2I_Byrack_Enable_IMM27_27 "绝缘采样使能位_IMM27";
CM_ SG_ 2332113835 M2I_Byrack_ReVeEnable_IMM27_27 "读取软件版本使能位_IMM27";
CM_ SG_ 2332113835 Reserved_27 "预留预留";
CM_ SG_ 2332113835 M2I_Byrack_IsPostTm_IMM27_27 "绝缘采样时间_IMM27";
CM_ SG_ 2332113835 M2I_Byrack_SysABStTm_IMM27_27 "电压稳定时间_IMM27";
CM_ SG_ 2332113836 CRC_M2I_Byrack_IMM27_28 "CRC校验_IMM27";
CM_ SG_ 2332113836 M2I_Byrack_HVS_IMM27_28 "绝缘测量电压_IMM27";
CM_ SG_ 2332113836 M2I_Byrack_Enable_IMM27_28 "绝缘采样使能位_IMM27";
CM_ SG_ 2332113836 M2I_Byrack_ReVeEnable_IMM27_28 "读取软件版本使能位_IMM27";
CM_ SG_ 2332113836 Reserved_28 "预留预留";
CM_ SG_ 2332113836 M2I_Byrack_IsPostTm_IMM27_28 "绝缘采样时间_IMM27";
CM_ SG_ 2332113836 M2I_Byrack_SysABStTm_IMM27_28 "电压稳定时间_IMM27";
CM_ SG_ 2332113837 CRC_M2I_Byrack_IMM27_29 "CRC校验_IMM27";
CM_ SG_ 2332113837 M2I_Byrack_HVS_IMM27_29 "绝缘测量电压_IMM27";
CM_ SG_ 2332113837 M2I_Byrack_Enable_IMM27_29 "绝缘采样使能位_IMM27";
CM_ SG_ 2332113837 M2I_Byrack_ReVeEnable_IMM27_29 "读取软件版本使能位_IMM27";
CM_ SG_ 2332113837 Reserved_29 "预留预留";
CM_ SG_ 2332113837 M2I_Byrack_IsPostTm_IMM27_29 "绝缘采样时间_IMM27";
CM_ SG_ 2332113837 M2I_Byrack_SysABStTm_IMM27_29 "电压稳定时间_IMM27";
CM_ SG_ 2332113838 CRC_M2I_Byrack_IMM27_30 "CRC校验_IMM27";
CM_ SG_ 2332113838 M2I_Byrack_HVS_IMM27_30 "绝缘测量电压_IMM27";
CM_ SG_ 2332113838 M2I_Byrack_Enable_IMM27_30 "绝缘采样使能位_IMM27";
CM_ SG_ 2332113838 M2I_Byrack_ReVeEnable_IMM27_30 "读取软件版本使能位_IMM27";
CM_ SG_ 2332113838 Reserved_30 "预留预留";
CM_ SG_ 2332113838 M2I_Byrack_IsPostTm_IMM27_30 "绝缘采样时间_IMM27";
CM_ SG_ 2332113838 M2I_Byrack_SysABStTm_IMM27_30 "电压稳定时间_IMM27";
CM_ SG_ 2332113839 CRC_M2I_Byrack_IMM27_31 "CRC校验_IMM27";
CM_ SG_ 2332113839 M2I_Byrack_HVS_IMM27_31 "绝缘测量电压_IMM27";
CM_ SG_ 2332113839 M2I_Byrack_Enable_IMM27_31 "绝缘采样使能位_IMM27";
CM_ SG_ 2332113839 M2I_Byrack_ReVeEnable_IMM27_31 "读取软件版本使能位_IMM27";
CM_ SG_ 2332113839 Reserved_31 "预留预留";
CM_ SG_ 2332113839 M2I_Byrack_IsPostTm_IMM27_31 "绝缘采样时间_IMM27";
CM_ SG_ 2332113839 M2I_Byrack_SysABStTm_IMM27_31 "电压稳定时间_IMM27";
CM_ SG_ 2332114065 CRC_M2I_Byrack_IMM28_01 "CRC校验_IMM28";
CM_ SG_ 2332114065 M2I_Byrack_HVS_IMM28_01 "绝缘测量电压_IMM28";
CM_ SG_ 2332114065 M2I_Byrack_Enable_IMM28_01 "绝缘采样使能位_IMM28";
CM_ SG_ 2332114065 M2I_Byrack_ReVeEnable_IMM28_01 "读取软件版本使能位_IMM28";
CM_ SG_ 2332114065 Reserved_01 "预留预留";
CM_ SG_ 2332114065 M2I_Byrack_IsPostTm_IMM28_01 "绝缘采样时间_IMM28";
CM_ SG_ 2332114065 M2I_Byrack_SysABStTm_IMM28_01 "电压稳定时间_IMM28";
CM_ SG_ 2332114066 CRC_M2I_Byrack_IMM28_02 "CRC校验_IMM28";
CM_ SG_ 2332114066 M2I_Byrack_HVS_IMM28_02 "绝缘测量电压_IMM28";
CM_ SG_ 2332114066 M2I_Byrack_Enable_IMM28_02 "绝缘采样使能位_IMM28";
CM_ SG_ 2332114066 M2I_Byrack_ReVeEnable_IMM28_02 "读取软件版本使能位_IMM28";
CM_ SG_ 2332114066 Reserved_02 "预留预留";
CM_ SG_ 2332114066 M2I_Byrack_IsPostTm_IMM28_02 "绝缘采样时间_IMM28";
CM_ SG_ 2332114066 M2I_Byrack_SysABStTm_IMM28_02 "电压稳定时间_IMM28";
CM_ SG_ 2332114067 CRC_M2I_Byrack_IMM28_03 "CRC校验_IMM28";
CM_ SG_ 2332114067 M2I_Byrack_HVS_IMM28_03 "绝缘测量电压_IMM28";
CM_ SG_ 2332114067 M2I_Byrack_Enable_IMM28_03 "绝缘采样使能位_IMM28";
CM_ SG_ 2332114067 M2I_Byrack_ReVeEnable_IMM28_03 "读取软件版本使能位_IMM28";
CM_ SG_ 2332114067 Reserved_03 "预留预留";
CM_ SG_ 2332114067 M2I_Byrack_IsPostTm_IMM28_03 "绝缘采样时间_IMM28";
CM_ SG_ 2332114067 M2I_Byrack_SysABStTm_IMM28_03 "电压稳定时间_IMM28";
CM_ SG_ 2332114068 CRC_M2I_Byrack_IMM28_04 "CRC校验_IMM28";
CM_ SG_ 2332114068 M2I_Byrack_HVS_IMM28_04 "绝缘测量电压_IMM28";
CM_ SG_ 2332114068 M2I_Byrack_Enable_IMM28_04 "绝缘采样使能位_IMM28";
CM_ SG_ 2332114068 M2I_Byrack_ReVeEnable_IMM28_04 "读取软件版本使能位_IMM28";
CM_ SG_ 2332114068 Reserved_04 "预留预留";
CM_ SG_ 2332114068 M2I_Byrack_IsPostTm_IMM28_04 "绝缘采样时间_IMM28";
CM_ SG_ 2332114068 M2I_Byrack_SysABStTm_IMM28_04 "电压稳定时间_IMM28";
CM_ SG_ 2332114069 CRC_M2I_Byrack_IMM28_05 "CRC校验_IMM28";
CM_ SG_ 2332114069 M2I_Byrack_HVS_IMM28_05 "绝缘测量电压_IMM28";
CM_ SG_ 2332114069 M2I_Byrack_Enable_IMM28_05 "绝缘采样使能位_IMM28";
CM_ SG_ 2332114069 M2I_Byrack_ReVeEnable_IMM28_05 "读取软件版本使能位_IMM28";
CM_ SG_ 2332114069 Reserved_05 "预留预留";
CM_ SG_ 2332114069 M2I_Byrack_IsPostTm_IMM28_05 "绝缘采样时间_IMM28";
CM_ SG_ 2332114069 M2I_Byrack_SysABStTm_IMM28_05 "电压稳定时间_IMM28";
CM_ SG_ 2332114070 CRC_M2I_Byrack_IMM28_06 "CRC校验_IMM28";
CM_ SG_ 2332114070 M2I_Byrack_HVS_IMM28_06 "绝缘测量电压_IMM28";
CM_ SG_ 2332114070 M2I_Byrack_Enable_IMM28_06 "绝缘采样使能位_IMM28";
CM_ SG_ 2332114070 M2I_Byrack_ReVeEnable_IMM28_06 "读取软件版本使能位_IMM28";
CM_ SG_ 2332114070 Reserved_06 "预留预留";
CM_ SG_ 2332114070 M2I_Byrack_IsPostTm_IMM28_06 "绝缘采样时间_IMM28";
CM_ SG_ 2332114070 M2I_Byrack_SysABStTm_IMM28_06 "电压稳定时间_IMM28";
CM_ SG_ 2332114071 CRC_M2I_Byrack_IMM28_07 "CRC校验_IMM28";
CM_ SG_ 2332114071 M2I_Byrack_HVS_IMM28_07 "绝缘测量电压_IMM28";
CM_ SG_ 2332114071 M2I_Byrack_Enable_IMM28_07 "绝缘采样使能位_IMM28";
CM_ SG_ 2332114071 M2I_Byrack_ReVeEnable_IMM28_07 "读取软件版本使能位_IMM28";
CM_ SG_ 2332114071 Reserved_07 "预留预留";
CM_ SG_ 2332114071 M2I_Byrack_IsPostTm_IMM28_07 "绝缘采样时间_IMM28";
CM_ SG_ 2332114071 M2I_Byrack_SysABStTm_IMM28_07 "电压稳定时间_IMM28";
CM_ SG_ 2332114072 CRC_M2I_Byrack_IMM28_08 "CRC校验_IMM28";
CM_ SG_ 2332114072 M2I_Byrack_HVS_IMM28_08 "绝缘测量电压_IMM28";
CM_ SG_ 2332114072 M2I_Byrack_Enable_IMM28_08 "绝缘采样使能位_IMM28";
CM_ SG_ 2332114072 M2I_Byrack_ReVeEnable_IMM28_08 "读取软件版本使能位_IMM28";
CM_ SG_ 2332114072 Reserved_08 "预留预留";
CM_ SG_ 2332114072 M2I_Byrack_IsPostTm_IMM28_08 "绝缘采样时间_IMM28";
CM_ SG_ 2332114072 M2I_Byrack_SysABStTm_IMM28_08 "电压稳定时间_IMM28";
CM_ SG_ 2332114073 CRC_M2I_Byrack_IMM28_09 "CRC校验_IMM28";
CM_ SG_ 2332114073 M2I_Byrack_HVS_IMM28_09 "绝缘测量电压_IMM28";
CM_ SG_ 2332114073 M2I_Byrack_Enable_IMM28_09 "绝缘采样使能位_IMM28";
CM_ SG_ 2332114073 M2I_Byrack_ReVeEnable_IMM28_09 "读取软件版本使能位_IMM28";
CM_ SG_ 2332114073 Reserved_09 "预留预留";
CM_ SG_ 2332114073 M2I_Byrack_IsPostTm_IMM28_09 "绝缘采样时间_IMM28";
CM_ SG_ 2332114073 M2I_Byrack_SysABStTm_IMM28_09 "电压稳定时间_IMM28";
CM_ SG_ 2332114074 CRC_M2I_Byrack_IMM28_10 "CRC校验_IMM28";
CM_ SG_ 2332114074 M2I_Byrack_HVS_IMM28_10 "绝缘测量电压_IMM28";
CM_ SG_ 2332114074 M2I_Byrack_Enable_IMM28_10 "绝缘采样使能位_IMM28";
CM_ SG_ 2332114074 M2I_Byrack_ReVeEnable_IMM28_10 "读取软件版本使能位_IMM28";
CM_ SG_ 2332114074 Reserved_10 "预留预留";
CM_ SG_ 2332114074 M2I_Byrack_IsPostTm_IMM28_10 "绝缘采样时间_IMM28";
CM_ SG_ 2332114074 M2I_Byrack_SysABStTm_IMM28_10 "电压稳定时间_IMM28";
CM_ SG_ 2332114075 CRC_M2I_Byrack_IMM28_11 "CRC校验_IMM28";
CM_ SG_ 2332114075 M2I_Byrack_HVS_IMM28_11 "绝缘测量电压_IMM28";
CM_ SG_ 2332114075 M2I_Byrack_Enable_IMM28_11 "绝缘采样使能位_IMM28";
CM_ SG_ 2332114075 M2I_Byrack_ReVeEnable_IMM28_11 "读取软件版本使能位_IMM28";
CM_ SG_ 2332114075 Reserved_11 "预留预留";
CM_ SG_ 2332114075 M2I_Byrack_IsPostTm_IMM28_11 "绝缘采样时间_IMM28";
CM_ SG_ 2332114075 M2I_Byrack_SysABStTm_IMM28_11 "电压稳定时间_IMM28";
CM_ SG_ 2332114076 CRC_M2I_Byrack_IMM28_12 "CRC校验_IMM28";
CM_ SG_ 2332114076 M2I_Byrack_HVS_IMM28_12 "绝缘测量电压_IMM28";
CM_ SG_ 2332114076 M2I_Byrack_Enable_IMM28_12 "绝缘采样使能位_IMM28";
CM_ SG_ 2332114076 M2I_Byrack_ReVeEnable_IMM28_12 "读取软件版本使能位_IMM28";
CM_ SG_ 2332114076 Reserved_12 "预留预留";
CM_ SG_ 2332114076 M2I_Byrack_IsPostTm_IMM28_12 "绝缘采样时间_IMM28";
CM_ SG_ 2332114076 M2I_Byrack_SysABStTm_IMM28_12 "电压稳定时间_IMM28";
CM_ SG_ 2332114077 CRC_M2I_Byrack_IMM28_13 "CRC校验_IMM28";
CM_ SG_ 2332114077 M2I_Byrack_HVS_IMM28_13 "绝缘测量电压_IMM28";
CM_ SG_ 2332114077 M2I_Byrack_Enable_IMM28_13 "绝缘采样使能位_IMM28";
CM_ SG_ 2332114077 M2I_Byrack_ReVeEnable_IMM28_13 "读取软件版本使能位_IMM28";
CM_ SG_ 2332114077 Reserved_13 "预留预留";
CM_ SG_ 2332114077 M2I_Byrack_IsPostTm_IMM28_13 "绝缘采样时间_IMM28";
CM_ SG_ 2332114077 M2I_Byrack_SysABStTm_IMM28_13 "电压稳定时间_IMM28";
CM_ SG_ 2332114078 CRC_M2I_Byrack_IMM28_14 "CRC校验_IMM28";
CM_ SG_ 2332114078 M2I_Byrack_HVS_IMM28_14 "绝缘测量电压_IMM28";
CM_ SG_ 2332114078 M2I_Byrack_Enable_IMM28_14 "绝缘采样使能位_IMM28";
CM_ SG_ 2332114078 M2I_Byrack_ReVeEnable_IMM28_14 "读取软件版本使能位_IMM28";
CM_ SG_ 2332114078 Reserved_14 "预留预留";
CM_ SG_ 2332114078 M2I_Byrack_IsPostTm_IMM28_14 "绝缘采样时间_IMM28";
CM_ SG_ 2332114078 M2I_Byrack_SysABStTm_IMM28_14 "电压稳定时间_IMM28";
CM_ SG_ 2332114079 CRC_M2I_Byrack_IMM28_15 "CRC校验_IMM28";
CM_ SG_ 2332114079 M2I_Byrack_HVS_IMM28_15 "绝缘测量电压_IMM28";
CM_ SG_ 2332114079 M2I_Byrack_Enable_IMM28_15 "绝缘采样使能位_IMM28";
CM_ SG_ 2332114079 M2I_Byrack_ReVeEnable_IMM28_15 "读取软件版本使能位_IMM28";
CM_ SG_ 2332114079 Reserved_15 "预留预留";
CM_ SG_ 2332114079 M2I_Byrack_IsPostTm_IMM28_15 "绝缘采样时间_IMM28";
CM_ SG_ 2332114079 M2I_Byrack_SysABStTm_IMM28_15 "电压稳定时间_IMM28";
CM_ SG_ 2332114080 CRC_M2I_Byrack_IMM28_16 "CRC校验_IMM28";
CM_ SG_ 2332114080 M2I_Byrack_HVS_IMM28_16 "绝缘测量电压_IMM28";
CM_ SG_ 2332114080 M2I_Byrack_Enable_IMM28_16 "绝缘采样使能位_IMM28";
CM_ SG_ 2332114080 M2I_Byrack_ReVeEnable_IMM28_16 "读取软件版本使能位_IMM28";
CM_ SG_ 2332114080 Reserved_16 "预留预留";
CM_ SG_ 2332114080 M2I_Byrack_IsPostTm_IMM28_16 "绝缘采样时间_IMM28";
CM_ SG_ 2332114080 M2I_Byrack_SysABStTm_IMM28_16 "电压稳定时间_IMM28";
CM_ SG_ 2332114081 CRC_M2I_Byrack_IMM28_17 "CRC校验_IMM28";
CM_ SG_ 2332114081 M2I_Byrack_HVS_IMM28_17 "绝缘测量电压_IMM28";
CM_ SG_ 2332114081 M2I_Byrack_Enable_IMM28_17 "绝缘采样使能位_IMM28";
CM_ SG_ 2332114081 M2I_Byrack_ReVeEnable_IMM28_17 "读取软件版本使能位_IMM28";
CM_ SG_ 2332114081 Reserved_17 "预留预留";
CM_ SG_ 2332114081 M2I_Byrack_IsPostTm_IMM28_17 "绝缘采样时间_IMM28";
CM_ SG_ 2332114081 M2I_Byrack_SysABStTm_IMM28_17 "电压稳定时间_IMM28";
CM_ SG_ 2332114082 CRC_M2I_Byrack_IMM28_18 "CRC校验_IMM28";
CM_ SG_ 2332114082 M2I_Byrack_HVS_IMM28_18 "绝缘测量电压_IMM28";
CM_ SG_ 2332114082 M2I_Byrack_Enable_IMM28_18 "绝缘采样使能位_IMM28";
CM_ SG_ 2332114082 M2I_Byrack_ReVeEnable_IMM28_18 "读取软件版本使能位_IMM28";
CM_ SG_ 2332114082 Reserved_18 "预留预留";
CM_ SG_ 2332114082 M2I_Byrack_IsPostTm_IMM28_18 "绝缘采样时间_IMM28";
CM_ SG_ 2332114082 M2I_Byrack_SysABStTm_IMM28_18 "电压稳定时间_IMM28";
CM_ SG_ 2332114083 CRC_M2I_Byrack_IMM28_19 "CRC校验_IMM28";
CM_ SG_ 2332114083 M2I_Byrack_HVS_IMM28_19 "绝缘测量电压_IMM28";
CM_ SG_ 2332114083 M2I_Byrack_Enable_IMM28_19 "绝缘采样使能位_IMM28";
CM_ SG_ 2332114083 M2I_Byrack_ReVeEnable_IMM28_19 "读取软件版本使能位_IMM28";
CM_ SG_ 2332114083 Reserved_19 "预留预留";
CM_ SG_ 2332114083 M2I_Byrack_IsPostTm_IMM28_19 "绝缘采样时间_IMM28";
CM_ SG_ 2332114083 M2I_Byrack_SysABStTm_IMM28_19 "电压稳定时间_IMM28";
CM_ SG_ 2332114084 CRC_M2I_Byrack_IMM28_20 "CRC校验_IMM28";
CM_ SG_ 2332114084 M2I_Byrack_HVS_IMM28_20 "绝缘测量电压_IMM28";
CM_ SG_ 2332114084 M2I_Byrack_Enable_IMM28_20 "绝缘采样使能位_IMM28";
CM_ SG_ 2332114084 M2I_Byrack_ReVeEnable_IMM28_20 "读取软件版本使能位_IMM28";
CM_ SG_ 2332114084 Reserved_20 "预留预留";
CM_ SG_ 2332114084 M2I_Byrack_IsPostTm_IMM28_20 "绝缘采样时间_IMM28";
CM_ SG_ 2332114084 M2I_Byrack_SysABStTm_IMM28_20 "电压稳定时间_IMM28";
CM_ SG_ 2332114085 CRC_M2I_Byrack_IMM28_21 "CRC校验_IMM28";
CM_ SG_ 2332114085 M2I_Byrack_HVS_IMM28_21 "绝缘测量电压_IMM28";
CM_ SG_ 2332114085 M2I_Byrack_Enable_IMM28_21 "绝缘采样使能位_IMM28";
CM_ SG_ 2332114085 M2I_Byrack_ReVeEnable_IMM28_21 "读取软件版本使能位_IMM28";
CM_ SG_ 2332114085 Reserved_21 "预留预留";
CM_ SG_ 2332114085 M2I_Byrack_IsPostTm_IMM28_21 "绝缘采样时间_IMM28";
CM_ SG_ 2332114085 M2I_Byrack_SysABStTm_IMM28_21 "电压稳定时间_IMM28";
CM_ SG_ 2332114086 CRC_M2I_Byrack_IMM28_22 "CRC校验_IMM28";
CM_ SG_ 2332114086 M2I_Byrack_HVS_IMM28_22 "绝缘测量电压_IMM28";
CM_ SG_ 2332114086 M2I_Byrack_Enable_IMM28_22 "绝缘采样使能位_IMM28";
CM_ SG_ 2332114086 M2I_Byrack_ReVeEnable_IMM28_22 "读取软件版本使能位_IMM28";
CM_ SG_ 2332114086 Reserved_22 "预留预留";
CM_ SG_ 2332114086 M2I_Byrack_IsPostTm_IMM28_22 "绝缘采样时间_IMM28";
CM_ SG_ 2332114086 M2I_Byrack_SysABStTm_IMM28_22 "电压稳定时间_IMM28";
CM_ SG_ 2332114087 CRC_M2I_Byrack_IMM28_23 "CRC校验_IMM28";
CM_ SG_ 2332114087 M2I_Byrack_HVS_IMM28_23 "绝缘测量电压_IMM28";
CM_ SG_ 2332114087 M2I_Byrack_Enable_IMM28_23 "绝缘采样使能位_IMM28";
CM_ SG_ 2332114087 M2I_Byrack_ReVeEnable_IMM28_23 "读取软件版本使能位_IMM28";
CM_ SG_ 2332114087 Reserved_23 "预留预留";
CM_ SG_ 2332114087 M2I_Byrack_IsPostTm_IMM28_23 "绝缘采样时间_IMM28";
CM_ SG_ 2332114087 M2I_Byrack_SysABStTm_IMM28_23 "电压稳定时间_IMM28";
CM_ SG_ 2332114088 CRC_M2I_Byrack_IMM28_24 "CRC校验_IMM28";
CM_ SG_ 2332114088 M2I_Byrack_HVS_IMM28_24 "绝缘测量电压_IMM28";
CM_ SG_ 2332114088 M2I_Byrack_Enable_IMM28_24 "绝缘采样使能位_IMM28";
CM_ SG_ 2332114088 M2I_Byrack_ReVeEnable_IMM28_24 "读取软件版本使能位_IMM28";
CM_ SG_ 2332114088 Reserved_24 "预留预留";
CM_ SG_ 2332114088 M2I_Byrack_IsPostTm_IMM28_24 "绝缘采样时间_IMM28";
CM_ SG_ 2332114088 M2I_Byrack_SysABStTm_IMM28_24 "电压稳定时间_IMM28";
CM_ SG_ 2332114089 CRC_M2I_Byrack_IMM28_25 "CRC校验_IMM28";
CM_ SG_ 2332114089 M2I_Byrack_HVS_IMM28_25 "绝缘测量电压_IMM28";
CM_ SG_ 2332114089 M2I_Byrack_Enable_IMM28_25 "绝缘采样使能位_IMM28";
CM_ SG_ 2332114089 M2I_Byrack_ReVeEnable_IMM28_25 "读取软件版本使能位_IMM28";
CM_ SG_ 2332114089 Reserved_25 "预留预留";
CM_ SG_ 2332114089 M2I_Byrack_IsPostTm_IMM28_25 "绝缘采样时间_IMM28";
CM_ SG_ 2332114089 M2I_Byrack_SysABStTm_IMM28_25 "电压稳定时间_IMM28";
CM_ SG_ 2332114090 CRC_M2I_Byrack_IMM28_26 "CRC校验_IMM28";
CM_ SG_ 2332114090 M2I_Byrack_HVS_IMM28_26 "绝缘测量电压_IMM28";
CM_ SG_ 2332114090 M2I_Byrack_Enable_IMM28_26 "绝缘采样使能位_IMM28";
CM_ SG_ 2332114090 M2I_Byrack_ReVeEnable_IMM28_26 "读取软件版本使能位_IMM28";
CM_ SG_ 2332114090 Reserved_26 "预留预留";
CM_ SG_ 2332114090 M2I_Byrack_IsPostTm_IMM28_26 "绝缘采样时间_IMM28";
CM_ SG_ 2332114090 M2I_Byrack_SysABStTm_IMM28_26 "电压稳定时间_IMM28";
CM_ SG_ 2332114091 CRC_M2I_Byrack_IMM28_27 "CRC校验_IMM28";
CM_ SG_ 2332114091 M2I_Byrack_HVS_IMM28_27 "绝缘测量电压_IMM28";
CM_ SG_ 2332114091 M2I_Byrack_Enable_IMM28_27 "绝缘采样使能位_IMM28";
CM_ SG_ 2332114091 M2I_Byrack_ReVeEnable_IMM28_27 "读取软件版本使能位_IMM28";
CM_ SG_ 2332114091 Reserved_27 "预留预留";
CM_ SG_ 2332114091 M2I_Byrack_IsPostTm_IMM28_27 "绝缘采样时间_IMM28";
CM_ SG_ 2332114091 M2I_Byrack_SysABStTm_IMM28_27 "电压稳定时间_IMM28";
CM_ SG_ 2332114092 CRC_M2I_Byrack_IMM28_28 "CRC校验_IMM28";
CM_ SG_ 2332114092 M2I_Byrack_HVS_IMM28_28 "绝缘测量电压_IMM28";
CM_ SG_ 2332114092 M2I_Byrack_Enable_IMM28_28 "绝缘采样使能位_IMM28";
CM_ SG_ 2332114092 M2I_Byrack_ReVeEnable_IMM28_28 "读取软件版本使能位_IMM28";
CM_ SG_ 2332114092 Reserved_28 "预留预留";
CM_ SG_ 2332114092 M2I_Byrack_IsPostTm_IMM28_28 "绝缘采样时间_IMM28";
CM_ SG_ 2332114092 M2I_Byrack_SysABStTm_IMM28_28 "电压稳定时间_IMM28";
CM_ SG_ 2332114093 CRC_M2I_Byrack_IMM28_29 "CRC校验_IMM28";
CM_ SG_ 2332114093 M2I_Byrack_HVS_IMM28_29 "绝缘测量电压_IMM28";
CM_ SG_ 2332114093 M2I_Byrack_Enable_IMM28_29 "绝缘采样使能位_IMM28";
CM_ SG_ 2332114093 M2I_Byrack_ReVeEnable_IMM28_29 "读取软件版本使能位_IMM28";
CM_ SG_ 2332114093 Reserved_29 "预留预留";
CM_ SG_ 2332114093 M2I_Byrack_IsPostTm_IMM28_29 "绝缘采样时间_IMM28";
CM_ SG_ 2332114093 M2I_Byrack_SysABStTm_IMM28_29 "电压稳定时间_IMM28";
CM_ SG_ 2332114094 CRC_M2I_Byrack_IMM28_30 "CRC校验_IMM28";
CM_ SG_ 2332114094 M2I_Byrack_HVS_IMM28_30 "绝缘测量电压_IMM28";
CM_ SG_ 2332114094 M2I_Byrack_Enable_IMM28_30 "绝缘采样使能位_IMM28";
CM_ SG_ 2332114094 M2I_Byrack_ReVeEnable_IMM28_30 "读取软件版本使能位_IMM28";
CM_ SG_ 2332114094 Reserved_30 "预留预留";
CM_ SG_ 2332114094 M2I_Byrack_IsPostTm_IMM28_30 "绝缘采样时间_IMM28";
CM_ SG_ 2332114094 M2I_Byrack_SysABStTm_IMM28_30 "电压稳定时间_IMM28";
CM_ SG_ 2332114095 CRC_M2I_Byrack_IMM28_31 "CRC校验_IMM28";
CM_ SG_ 2332114095 M2I_Byrack_HVS_IMM28_31 "绝缘测量电压_IMM28";
CM_ SG_ 2332114095 M2I_Byrack_Enable_IMM28_31 "绝缘采样使能位_IMM28";
CM_ SG_ 2332114095 M2I_Byrack_ReVeEnable_IMM28_31 "读取软件版本使能位_IMM28";
CM_ SG_ 2332114095 Reserved_31 "预留预留";
CM_ SG_ 2332114095 M2I_Byrack_IsPostTm_IMM28_31 "绝缘采样时间_IMM28";
CM_ SG_ 2332114095 M2I_Byrack_SysABStTm_IMM28_31 "电压稳定时间_IMM28";
CM_ SG_ 2332114321 CRC_M2I_Byrack_IMM29_01 "CRC校验_IMM29";
CM_ SG_ 2332114321 M2I_Byrack_HVS_IMM29_01 "绝缘测量电压_IMM29";
CM_ SG_ 2332114321 M2I_Byrack_Enable_IMM29_01 "绝缘采样使能位_IMM29";
CM_ SG_ 2332114321 M2I_Byrack_ReVeEnable_IMM29_01 "读取软件版本使能位_IMM29";
CM_ SG_ 2332114321 Reserved_01 "预留预留";
CM_ SG_ 2332114321 M2I_Byrack_IsPostTm_IMM29_01 "绝缘采样时间_IMM29";
CM_ SG_ 2332114321 M2I_Byrack_SysABStTm_IMM29_01 "电压稳定时间_IMM29";
CM_ SG_ 2332114322 CRC_M2I_Byrack_IMM29_02 "CRC校验_IMM29";
CM_ SG_ 2332114322 M2I_Byrack_HVS_IMM29_02 "绝缘测量电压_IMM29";
CM_ SG_ 2332114322 M2I_Byrack_Enable_IMM29_02 "绝缘采样使能位_IMM29";
CM_ SG_ 2332114322 M2I_Byrack_ReVeEnable_IMM29_02 "读取软件版本使能位_IMM29";
CM_ SG_ 2332114322 Reserved_02 "预留预留";
CM_ SG_ 2332114322 M2I_Byrack_IsPostTm_IMM29_02 "绝缘采样时间_IMM29";
CM_ SG_ 2332114322 M2I_Byrack_SysABStTm_IMM29_02 "电压稳定时间_IMM29";
CM_ SG_ 2332114323 CRC_M2I_Byrack_IMM29_03 "CRC校验_IMM29";
CM_ SG_ 2332114323 M2I_Byrack_HVS_IMM29_03 "绝缘测量电压_IMM29";
CM_ SG_ 2332114323 M2I_Byrack_Enable_IMM29_03 "绝缘采样使能位_IMM29";
CM_ SG_ 2332114323 M2I_Byrack_ReVeEnable_IMM29_03 "读取软件版本使能位_IMM29";
CM_ SG_ 2332114323 Reserved_03 "预留预留";
CM_ SG_ 2332114323 M2I_Byrack_IsPostTm_IMM29_03 "绝缘采样时间_IMM29";
CM_ SG_ 2332114323 M2I_Byrack_SysABStTm_IMM29_03 "电压稳定时间_IMM29";
CM_ SG_ 2332114324 CRC_M2I_Byrack_IMM29_04 "CRC校验_IMM29";
CM_ SG_ 2332114324 M2I_Byrack_HVS_IMM29_04 "绝缘测量电压_IMM29";
CM_ SG_ 2332114324 M2I_Byrack_Enable_IMM29_04 "绝缘采样使能位_IMM29";
CM_ SG_ 2332114324 M2I_Byrack_ReVeEnable_IMM29_04 "读取软件版本使能位_IMM29";
CM_ SG_ 2332114324 Reserved_04 "预留预留";
CM_ SG_ 2332114324 M2I_Byrack_IsPostTm_IMM29_04 "绝缘采样时间_IMM29";
CM_ SG_ 2332114324 M2I_Byrack_SysABStTm_IMM29_04 "电压稳定时间_IMM29";
CM_ SG_ 2332114325 CRC_M2I_Byrack_IMM29_05 "CRC校验_IMM29";
CM_ SG_ 2332114325 M2I_Byrack_HVS_IMM29_05 "绝缘测量电压_IMM29";
CM_ SG_ 2332114325 M2I_Byrack_Enable_IMM29_05 "绝缘采样使能位_IMM29";
CM_ SG_ 2332114325 M2I_Byrack_ReVeEnable_IMM29_05 "读取软件版本使能位_IMM29";
CM_ SG_ 2332114325 Reserved_05 "预留预留";
CM_ SG_ 2332114325 M2I_Byrack_IsPostTm_IMM29_05 "绝缘采样时间_IMM29";
CM_ SG_ 2332114325 M2I_Byrack_SysABStTm_IMM29_05 "电压稳定时间_IMM29";
CM_ SG_ 2332114326 CRC_M2I_Byrack_IMM29_06 "CRC校验_IMM29";
CM_ SG_ 2332114326 M2I_Byrack_HVS_IMM29_06 "绝缘测量电压_IMM29";
CM_ SG_ 2332114326 M2I_Byrack_Enable_IMM29_06 "绝缘采样使能位_IMM29";
CM_ SG_ 2332114326 M2I_Byrack_ReVeEnable_IMM29_06 "读取软件版本使能位_IMM29";
CM_ SG_ 2332114326 Reserved_06 "预留预留";
CM_ SG_ 2332114326 M2I_Byrack_IsPostTm_IMM29_06 "绝缘采样时间_IMM29";
CM_ SG_ 2332114326 M2I_Byrack_SysABStTm_IMM29_06 "电压稳定时间_IMM29";
CM_ SG_ 2332114327 CRC_M2I_Byrack_IMM29_07 "CRC校验_IMM29";
CM_ SG_ 2332114327 M2I_Byrack_HVS_IMM29_07 "绝缘测量电压_IMM29";
CM_ SG_ 2332114327 M2I_Byrack_Enable_IMM29_07 "绝缘采样使能位_IMM29";
CM_ SG_ 2332114327 M2I_Byrack_ReVeEnable_IMM29_07 "读取软件版本使能位_IMM29";
CM_ SG_ 2332114327 Reserved_07 "预留预留";
CM_ SG_ 2332114327 M2I_Byrack_IsPostTm_IMM29_07 "绝缘采样时间_IMM29";
CM_ SG_ 2332114327 M2I_Byrack_SysABStTm_IMM29_07 "电压稳定时间_IMM29";
CM_ SG_ 2332114328 CRC_M2I_Byrack_IMM29_08 "CRC校验_IMM29";
CM_ SG_ 2332114328 M2I_Byrack_HVS_IMM29_08 "绝缘测量电压_IMM29";
CM_ SG_ 2332114328 M2I_Byrack_Enable_IMM29_08 "绝缘采样使能位_IMM29";
CM_ SG_ 2332114328 M2I_Byrack_ReVeEnable_IMM29_08 "读取软件版本使能位_IMM29";
CM_ SG_ 2332114328 Reserved_08 "预留预留";
CM_ SG_ 2332114328 M2I_Byrack_IsPostTm_IMM29_08 "绝缘采样时间_IMM29";
CM_ SG_ 2332114328 M2I_Byrack_SysABStTm_IMM29_08 "电压稳定时间_IMM29";
CM_ SG_ 2332114329 CRC_M2I_Byrack_IMM29_09 "CRC校验_IMM29";
CM_ SG_ 2332114329 M2I_Byrack_HVS_IMM29_09 "绝缘测量电压_IMM29";
CM_ SG_ 2332114329 M2I_Byrack_Enable_IMM29_09 "绝缘采样使能位_IMM29";
CM_ SG_ 2332114329 M2I_Byrack_ReVeEnable_IMM29_09 "读取软件版本使能位_IMM29";
CM_ SG_ 2332114329 Reserved_09 "预留预留";
CM_ SG_ 2332114329 M2I_Byrack_IsPostTm_IMM29_09 "绝缘采样时间_IMM29";
CM_ SG_ 2332114329 M2I_Byrack_SysABStTm_IMM29_09 "电压稳定时间_IMM29";
CM_ SG_ 2332114330 CRC_M2I_Byrack_IMM29_10 "CRC校验_IMM29";
CM_ SG_ 2332114330 M2I_Byrack_HVS_IMM29_10 "绝缘测量电压_IMM29";
CM_ SG_ 2332114330 M2I_Byrack_Enable_IMM29_10 "绝缘采样使能位_IMM29";
CM_ SG_ 2332114330 M2I_Byrack_ReVeEnable_IMM29_10 "读取软件版本使能位_IMM29";
CM_ SG_ 2332114330 Reserved_10 "预留预留";
CM_ SG_ 2332114330 M2I_Byrack_IsPostTm_IMM29_10 "绝缘采样时间_IMM29";
CM_ SG_ 2332114330 M2I_Byrack_SysABStTm_IMM29_10 "电压稳定时间_IMM29";
CM_ SG_ 2332114331 CRC_M2I_Byrack_IMM29_11 "CRC校验_IMM29";
CM_ SG_ 2332114331 M2I_Byrack_HVS_IMM29_11 "绝缘测量电压_IMM29";
CM_ SG_ 2332114331 M2I_Byrack_Enable_IMM29_11 "绝缘采样使能位_IMM29";
CM_ SG_ 2332114331 M2I_Byrack_ReVeEnable_IMM29_11 "读取软件版本使能位_IMM29";
CM_ SG_ 2332114331 Reserved_11 "预留预留";
CM_ SG_ 2332114331 M2I_Byrack_IsPostTm_IMM29_11 "绝缘采样时间_IMM29";
CM_ SG_ 2332114331 M2I_Byrack_SysABStTm_IMM29_11 "电压稳定时间_IMM29";
CM_ SG_ 2332114332 CRC_M2I_Byrack_IMM29_12 "CRC校验_IMM29";
CM_ SG_ 2332114332 M2I_Byrack_HVS_IMM29_12 "绝缘测量电压_IMM29";
CM_ SG_ 2332114332 M2I_Byrack_Enable_IMM29_12 "绝缘采样使能位_IMM29";
CM_ SG_ 2332114332 M2I_Byrack_ReVeEnable_IMM29_12 "读取软件版本使能位_IMM29";
CM_ SG_ 2332114332 Reserved_12 "预留预留";
CM_ SG_ 2332114332 M2I_Byrack_IsPostTm_IMM29_12 "绝缘采样时间_IMM29";
CM_ SG_ 2332114332 M2I_Byrack_SysABStTm_IMM29_12 "电压稳定时间_IMM29";
CM_ SG_ 2332114333 CRC_M2I_Byrack_IMM29_13 "CRC校验_IMM29";
CM_ SG_ 2332114333 M2I_Byrack_HVS_IMM29_13 "绝缘测量电压_IMM29";
CM_ SG_ 2332114333 M2I_Byrack_Enable_IMM29_13 "绝缘采样使能位_IMM29";
CM_ SG_ 2332114333 M2I_Byrack_ReVeEnable_IMM29_13 "读取软件版本使能位_IMM29";
CM_ SG_ 2332114333 Reserved_13 "预留预留";
CM_ SG_ 2332114333 M2I_Byrack_IsPostTm_IMM29_13 "绝缘采样时间_IMM29";
CM_ SG_ 2332114333 M2I_Byrack_SysABStTm_IMM29_13 "电压稳定时间_IMM29";
CM_ SG_ 2332114334 CRC_M2I_Byrack_IMM29_14 "CRC校验_IMM29";
CM_ SG_ 2332114334 M2I_Byrack_HVS_IMM29_14 "绝缘测量电压_IMM29";
CM_ SG_ 2332114334 M2I_Byrack_Enable_IMM29_14 "绝缘采样使能位_IMM29";
CM_ SG_ 2332114334 M2I_Byrack_ReVeEnable_IMM29_14 "读取软件版本使能位_IMM29";
CM_ SG_ 2332114334 Reserved_14 "预留预留";
CM_ SG_ 2332114334 M2I_Byrack_IsPostTm_IMM29_14 "绝缘采样时间_IMM29";
CM_ SG_ 2332114334 M2I_Byrack_SysABStTm_IMM29_14 "电压稳定时间_IMM29";
CM_ SG_ 2332114335 CRC_M2I_Byrack_IMM29_15 "CRC校验_IMM29";
CM_ SG_ 2332114335 M2I_Byrack_HVS_IMM29_15 "绝缘测量电压_IMM29";
CM_ SG_ 2332114335 M2I_Byrack_Enable_IMM29_15 "绝缘采样使能位_IMM29";
CM_ SG_ 2332114335 M2I_Byrack_ReVeEnable_IMM29_15 "读取软件版本使能位_IMM29";
CM_ SG_ 2332114335 Reserved_15 "预留预留";
CM_ SG_ 2332114335 M2I_Byrack_IsPostTm_IMM29_15 "绝缘采样时间_IMM29";
CM_ SG_ 2332114335 M2I_Byrack_SysABStTm_IMM29_15 "电压稳定时间_IMM29";
CM_ SG_ 2332114336 CRC_M2I_Byrack_IMM29_16 "CRC校验_IMM29";
CM_ SG_ 2332114336 M2I_Byrack_HVS_IMM29_16 "绝缘测量电压_IMM29";
CM_ SG_ 2332114336 M2I_Byrack_Enable_IMM29_16 "绝缘采样使能位_IMM29";
CM_ SG_ 2332114336 M2I_Byrack_ReVeEnable_IMM29_16 "读取软件版本使能位_IMM29";
CM_ SG_ 2332114336 Reserved_16 "预留预留";
CM_ SG_ 2332114336 M2I_Byrack_IsPostTm_IMM29_16 "绝缘采样时间_IMM29";
CM_ SG_ 2332114336 M2I_Byrack_SysABStTm_IMM29_16 "电压稳定时间_IMM29";
CM_ SG_ 2332114337 CRC_M2I_Byrack_IMM29_17 "CRC校验_IMM29";
CM_ SG_ 2332114337 M2I_Byrack_HVS_IMM29_17 "绝缘测量电压_IMM29";
CM_ SG_ 2332114337 M2I_Byrack_Enable_IMM29_17 "绝缘采样使能位_IMM29";
CM_ SG_ 2332114337 M2I_Byrack_ReVeEnable_IMM29_17 "读取软件版本使能位_IMM29";
CM_ SG_ 2332114337 Reserved_17 "预留预留";
CM_ SG_ 2332114337 M2I_Byrack_IsPostTm_IMM29_17 "绝缘采样时间_IMM29";
CM_ SG_ 2332114337 M2I_Byrack_SysABStTm_IMM29_17 "电压稳定时间_IMM29";
CM_ SG_ 2332114338 CRC_M2I_Byrack_IMM29_18 "CRC校验_IMM29";
CM_ SG_ 2332114338 M2I_Byrack_HVS_IMM29_18 "绝缘测量电压_IMM29";
CM_ SG_ 2332114338 M2I_Byrack_Enable_IMM29_18 "绝缘采样使能位_IMM29";
CM_ SG_ 2332114338 M2I_Byrack_ReVeEnable_IMM29_18 "读取软件版本使能位_IMM29";
CM_ SG_ 2332114338 Reserved_18 "预留预留";
CM_ SG_ 2332114338 M2I_Byrack_IsPostTm_IMM29_18 "绝缘采样时间_IMM29";
CM_ SG_ 2332114338 M2I_Byrack_SysABStTm_IMM29_18 "电压稳定时间_IMM29";
CM_ SG_ 2332114339 CRC_M2I_Byrack_IMM29_19 "CRC校验_IMM29";
CM_ SG_ 2332114339 M2I_Byrack_HVS_IMM29_19 "绝缘测量电压_IMM29";
CM_ SG_ 2332114339 M2I_Byrack_Enable_IMM29_19 "绝缘采样使能位_IMM29";
CM_ SG_ 2332114339 M2I_Byrack_ReVeEnable_IMM29_19 "读取软件版本使能位_IMM29";
CM_ SG_ 2332114339 Reserved_19 "预留预留";
CM_ SG_ 2332114339 M2I_Byrack_IsPostTm_IMM29_19 "绝缘采样时间_IMM29";
CM_ SG_ 2332114339 M2I_Byrack_SysABStTm_IMM29_19 "电压稳定时间_IMM29";
CM_ SG_ 2332114340 CRC_M2I_Byrack_IMM29_20 "CRC校验_IMM29";
CM_ SG_ 2332114340 M2I_Byrack_HVS_IMM29_20 "绝缘测量电压_IMM29";
CM_ SG_ 2332114340 M2I_Byrack_Enable_IMM29_20 "绝缘采样使能位_IMM29";
CM_ SG_ 2332114340 M2I_Byrack_ReVeEnable_IMM29_20 "读取软件版本使能位_IMM29";
CM_ SG_ 2332114340 Reserved_20 "预留预留";
CM_ SG_ 2332114340 M2I_Byrack_IsPostTm_IMM29_20 "绝缘采样时间_IMM29";
CM_ SG_ 2332114340 M2I_Byrack_SysABStTm_IMM29_20 "电压稳定时间_IMM29";
CM_ SG_ 2332114341 CRC_M2I_Byrack_IMM29_21 "CRC校验_IMM29";
CM_ SG_ 2332114341 M2I_Byrack_HVS_IMM29_21 "绝缘测量电压_IMM29";
CM_ SG_ 2332114341 M2I_Byrack_Enable_IMM29_21 "绝缘采样使能位_IMM29";
CM_ SG_ 2332114341 M2I_Byrack_ReVeEnable_IMM29_21 "读取软件版本使能位_IMM29";
CM_ SG_ 2332114341 Reserved_21 "预留预留";
CM_ SG_ 2332114341 M2I_Byrack_IsPostTm_IMM29_21 "绝缘采样时间_IMM29";
CM_ SG_ 2332114341 M2I_Byrack_SysABStTm_IMM29_21 "电压稳定时间_IMM29";
CM_ SG_ 2332114342 CRC_M2I_Byrack_IMM29_22 "CRC校验_IMM29";
CM_ SG_ 2332114342 M2I_Byrack_HVS_IMM29_22 "绝缘测量电压_IMM29";
CM_ SG_ 2332114342 M2I_Byrack_Enable_IMM29_22 "绝缘采样使能位_IMM29";
CM_ SG_ 2332114342 M2I_Byrack_ReVeEnable_IMM29_22 "读取软件版本使能位_IMM29";
CM_ SG_ 2332114342 Reserved_22 "预留预留";
CM_ SG_ 2332114342 M2I_Byrack_IsPostTm_IMM29_22 "绝缘采样时间_IMM29";
CM_ SG_ 2332114342 M2I_Byrack_SysABStTm_IMM29_22 "电压稳定时间_IMM29";
CM_ SG_ 2332114343 CRC_M2I_Byrack_IMM29_23 "CRC校验_IMM29";
CM_ SG_ 2332114343 M2I_Byrack_HVS_IMM29_23 "绝缘测量电压_IMM29";
CM_ SG_ 2332114343 M2I_Byrack_Enable_IMM29_23 "绝缘采样使能位_IMM29";
CM_ SG_ 2332114343 M2I_Byrack_ReVeEnable_IMM29_23 "读取软件版本使能位_IMM29";
CM_ SG_ 2332114343 Reserved_23 "预留预留";
CM_ SG_ 2332114343 M2I_Byrack_IsPostTm_IMM29_23 "绝缘采样时间_IMM29";
CM_ SG_ 2332114343 M2I_Byrack_SysABStTm_IMM29_23 "电压稳定时间_IMM29";
CM_ SG_ 2332114344 CRC_M2I_Byrack_IMM29_24 "CRC校验_IMM29";
CM_ SG_ 2332114344 M2I_Byrack_HVS_IMM29_24 "绝缘测量电压_IMM29";
CM_ SG_ 2332114344 M2I_Byrack_Enable_IMM29_24 "绝缘采样使能位_IMM29";
CM_ SG_ 2332114344 M2I_Byrack_ReVeEnable_IMM29_24 "读取软件版本使能位_IMM29";
CM_ SG_ 2332114344 Reserved_24 "预留预留";
CM_ SG_ 2332114344 M2I_Byrack_IsPostTm_IMM29_24 "绝缘采样时间_IMM29";
CM_ SG_ 2332114344 M2I_Byrack_SysABStTm_IMM29_24 "电压稳定时间_IMM29";
CM_ SG_ 2332114345 CRC_M2I_Byrack_IMM29_25 "CRC校验_IMM29";
CM_ SG_ 2332114345 M2I_Byrack_HVS_IMM29_25 "绝缘测量电压_IMM29";
CM_ SG_ 2332114345 M2I_Byrack_Enable_IMM29_25 "绝缘采样使能位_IMM29";
CM_ SG_ 2332114345 M2I_Byrack_ReVeEnable_IMM29_25 "读取软件版本使能位_IMM29";
CM_ SG_ 2332114345 Reserved_25 "预留预留";
CM_ SG_ 2332114345 M2I_Byrack_IsPostTm_IMM29_25 "绝缘采样时间_IMM29";
CM_ SG_ 2332114345 M2I_Byrack_SysABStTm_IMM29_25 "电压稳定时间_IMM29";
CM_ SG_ 2332114346 CRC_M2I_Byrack_IMM29_26 "CRC校验_IMM29";
CM_ SG_ 2332114346 M2I_Byrack_HVS_IMM29_26 "绝缘测量电压_IMM29";
CM_ SG_ 2332114346 M2I_Byrack_Enable_IMM29_26 "绝缘采样使能位_IMM29";
CM_ SG_ 2332114346 M2I_Byrack_ReVeEnable_IMM29_26 "读取软件版本使能位_IMM29";
CM_ SG_ 2332114346 Reserved_26 "预留预留";
CM_ SG_ 2332114346 M2I_Byrack_IsPostTm_IMM29_26 "绝缘采样时间_IMM29";
CM_ SG_ 2332114346 M2I_Byrack_SysABStTm_IMM29_26 "电压稳定时间_IMM29";
CM_ SG_ 2332114347 CRC_M2I_Byrack_IMM29_27 "CRC校验_IMM29";
CM_ SG_ 2332114347 M2I_Byrack_HVS_IMM29_27 "绝缘测量电压_IMM29";
CM_ SG_ 2332114347 M2I_Byrack_Enable_IMM29_27 "绝缘采样使能位_IMM29";
CM_ SG_ 2332114347 M2I_Byrack_ReVeEnable_IMM29_27 "读取软件版本使能位_IMM29";
CM_ SG_ 2332114347 Reserved_27 "预留预留";
CM_ SG_ 2332114347 M2I_Byrack_IsPostTm_IMM29_27 "绝缘采样时间_IMM29";
CM_ SG_ 2332114347 M2I_Byrack_SysABStTm_IMM29_27 "电压稳定时间_IMM29";
CM_ SG_ 2332114348 CRC_M2I_Byrack_IMM29_28 "CRC校验_IMM29";
CM_ SG_ 2332114348 M2I_Byrack_HVS_IMM29_28 "绝缘测量电压_IMM29";
CM_ SG_ 2332114348 M2I_Byrack_Enable_IMM29_28 "绝缘采样使能位_IMM29";
CM_ SG_ 2332114348 M2I_Byrack_ReVeEnable_IMM29_28 "读取软件版本使能位_IMM29";
CM_ SG_ 2332114348 Reserved_28 "预留预留";
CM_ SG_ 2332114348 M2I_Byrack_IsPostTm_IMM29_28 "绝缘采样时间_IMM29";
CM_ SG_ 2332114348 M2I_Byrack_SysABStTm_IMM29_28 "电压稳定时间_IMM29";
CM_ SG_ 2332114349 CRC_M2I_Byrack_IMM29_29 "CRC校验_IMM29";
CM_ SG_ 2332114349 M2I_Byrack_HVS_IMM29_29 "绝缘测量电压_IMM29";
CM_ SG_ 2332114349 M2I_Byrack_Enable_IMM29_29 "绝缘采样使能位_IMM29";
CM_ SG_ 2332114349 M2I_Byrack_ReVeEnable_IMM29_29 "读取软件版本使能位_IMM29";
CM_ SG_ 2332114349 Reserved_29 "预留预留";
CM_ SG_ 2332114349 M2I_Byrack_IsPostTm_IMM29_29 "绝缘采样时间_IMM29";
CM_ SG_ 2332114349 M2I_Byrack_SysABStTm_IMM29_29 "电压稳定时间_IMM29";
CM_ SG_ 2332114350 CRC_M2I_Byrack_IMM29_30 "CRC校验_IMM29";
CM_ SG_ 2332114350 M2I_Byrack_HVS_IMM29_30 "绝缘测量电压_IMM29";
CM_ SG_ 2332114350 M2I_Byrack_Enable_IMM29_30 "绝缘采样使能位_IMM29";
CM_ SG_ 2332114350 M2I_Byrack_ReVeEnable_IMM29_30 "读取软件版本使能位_IMM29";
CM_ SG_ 2332114350 Reserved_30 "预留预留";
CM_ SG_ 2332114350 M2I_Byrack_IsPostTm_IMM29_30 "绝缘采样时间_IMM29";
CM_ SG_ 2332114350 M2I_Byrack_SysABStTm_IMM29_30 "电压稳定时间_IMM29";
CM_ SG_ 2332114351 CRC_M2I_Byrack_IMM29_31 "CRC校验_IMM29";
CM_ SG_ 2332114351 M2I_Byrack_HVS_IMM29_31 "绝缘测量电压_IMM29";
CM_ SG_ 2332114351 M2I_Byrack_Enable_IMM29_31 "绝缘采样使能位_IMM29";
CM_ SG_ 2332114351 M2I_Byrack_ReVeEnable_IMM29_31 "读取软件版本使能位_IMM29";
CM_ SG_ 2332114351 Reserved_31 "预留预留";
CM_ SG_ 2332114351 M2I_Byrack_IsPostTm_IMM29_31 "绝缘采样时间_IMM29";
CM_ SG_ 2332114351 M2I_Byrack_SysABStTm_IMM29_31 "电压稳定时间_IMM29";
CM_ SG_ 2332114577 CRC_M2I_Byrack_IMM30_01 "CRC校验_IMM30";
CM_ SG_ 2332114577 M2I_Byrack_HVS_IMM30_01 "绝缘测量电压_IMM30";
CM_ SG_ 2332114577 M2I_Byrack_Enable_IMM30_01 "绝缘采样使能位_IMM30";
CM_ SG_ 2332114577 M2I_Byrack_ReVeEnable_IMM30_01 "读取软件版本使能位_IMM30";
CM_ SG_ 2332114577 Reserved_01 "预留预留";
CM_ SG_ 2332114577 M2I_Byrack_IsPostTm_IMM30_01 "绝缘采样时间_IMM30";
CM_ SG_ 2332114577 M2I_Byrack_SysABStTm_IMM30_01 "电压稳定时间_IMM30";
CM_ SG_ 2332114578 CRC_M2I_Byrack_IMM30_02 "CRC校验_IMM30";
CM_ SG_ 2332114578 M2I_Byrack_HVS_IMM30_02 "绝缘测量电压_IMM30";
CM_ SG_ 2332114578 M2I_Byrack_Enable_IMM30_02 "绝缘采样使能位_IMM30";
CM_ SG_ 2332114578 M2I_Byrack_ReVeEnable_IMM30_02 "读取软件版本使能位_IMM30";
CM_ SG_ 2332114578 Reserved_02 "预留预留";
CM_ SG_ 2332114578 M2I_Byrack_IsPostTm_IMM30_02 "绝缘采样时间_IMM30";
CM_ SG_ 2332114578 M2I_Byrack_SysABStTm_IMM30_02 "电压稳定时间_IMM30";
CM_ SG_ 2332114579 CRC_M2I_Byrack_IMM30_03 "CRC校验_IMM30";
CM_ SG_ 2332114579 M2I_Byrack_HVS_IMM30_03 "绝缘测量电压_IMM30";
CM_ SG_ 2332114579 M2I_Byrack_Enable_IMM30_03 "绝缘采样使能位_IMM30";
CM_ SG_ 2332114579 M2I_Byrack_ReVeEnable_IMM30_03 "读取软件版本使能位_IMM30";
CM_ SG_ 2332114579 Reserved_03 "预留预留";
CM_ SG_ 2332114579 M2I_Byrack_IsPostTm_IMM30_03 "绝缘采样时间_IMM30";
CM_ SG_ 2332114579 M2I_Byrack_SysABStTm_IMM30_03 "电压稳定时间_IMM30";
CM_ SG_ 2332114580 CRC_M2I_Byrack_IMM30_04 "CRC校验_IMM30";
CM_ SG_ 2332114580 M2I_Byrack_HVS_IMM30_04 "绝缘测量电压_IMM30";
CM_ SG_ 2332114580 M2I_Byrack_Enable_IMM30_04 "绝缘采样使能位_IMM30";
CM_ SG_ 2332114580 M2I_Byrack_ReVeEnable_IMM30_04 "读取软件版本使能位_IMM30";
CM_ SG_ 2332114580 Reserved_04 "预留预留";
CM_ SG_ 2332114580 M2I_Byrack_IsPostTm_IMM30_04 "绝缘采样时间_IMM30";
CM_ SG_ 2332114580 M2I_Byrack_SysABStTm_IMM30_04 "电压稳定时间_IMM30";
CM_ SG_ 2332114581 CRC_M2I_Byrack_IMM30_05 "CRC校验_IMM30";
CM_ SG_ 2332114581 M2I_Byrack_HVS_IMM30_05 "绝缘测量电压_IMM30";
CM_ SG_ 2332114581 M2I_Byrack_Enable_IMM30_05 "绝缘采样使能位_IMM30";
CM_ SG_ 2332114581 M2I_Byrack_ReVeEnable_IMM30_05 "读取软件版本使能位_IMM30";
CM_ SG_ 2332114581 Reserved_05 "预留预留";
CM_ SG_ 2332114581 M2I_Byrack_IsPostTm_IMM30_05 "绝缘采样时间_IMM30";
CM_ SG_ 2332114581 M2I_Byrack_SysABStTm_IMM30_05 "电压稳定时间_IMM30";
CM_ SG_ 2332114582 CRC_M2I_Byrack_IMM30_06 "CRC校验_IMM30";
CM_ SG_ 2332114582 M2I_Byrack_HVS_IMM30_06 "绝缘测量电压_IMM30";
CM_ SG_ 2332114582 M2I_Byrack_Enable_IMM30_06 "绝缘采样使能位_IMM30";
CM_ SG_ 2332114582 M2I_Byrack_ReVeEnable_IMM30_06 "读取软件版本使能位_IMM30";
CM_ SG_ 2332114582 Reserved_06 "预留预留";
CM_ SG_ 2332114582 M2I_Byrack_IsPostTm_IMM30_06 "绝缘采样时间_IMM30";
CM_ SG_ 2332114582 M2I_Byrack_SysABStTm_IMM30_06 "电压稳定时间_IMM30";
CM_ SG_ 2332114583 CRC_M2I_Byrack_IMM30_07 "CRC校验_IMM30";
CM_ SG_ 2332114583 M2I_Byrack_HVS_IMM30_07 "绝缘测量电压_IMM30";
CM_ SG_ 2332114583 M2I_Byrack_Enable_IMM30_07 "绝缘采样使能位_IMM30";
CM_ SG_ 2332114583 M2I_Byrack_ReVeEnable_IMM30_07 "读取软件版本使能位_IMM30";
CM_ SG_ 2332114583 Reserved_07 "预留预留";
CM_ SG_ 2332114583 M2I_Byrack_IsPostTm_IMM30_07 "绝缘采样时间_IMM30";
CM_ SG_ 2332114583 M2I_Byrack_SysABStTm_IMM30_07 "电压稳定时间_IMM30";
CM_ SG_ 2332114584 CRC_M2I_Byrack_IMM30_08 "CRC校验_IMM30";
CM_ SG_ 2332114584 M2I_Byrack_HVS_IMM30_08 "绝缘测量电压_IMM30";
CM_ SG_ 2332114584 M2I_Byrack_Enable_IMM30_08 "绝缘采样使能位_IMM30";
CM_ SG_ 2332114584 M2I_Byrack_ReVeEnable_IMM30_08 "读取软件版本使能位_IMM30";
CM_ SG_ 2332114584 Reserved_08 "预留预留";
CM_ SG_ 2332114584 M2I_Byrack_IsPostTm_IMM30_08 "绝缘采样时间_IMM30";
CM_ SG_ 2332114584 M2I_Byrack_SysABStTm_IMM30_08 "电压稳定时间_IMM30";
CM_ SG_ 2332114585 CRC_M2I_Byrack_IMM30_09 "CRC校验_IMM30";
CM_ SG_ 2332114585 M2I_Byrack_HVS_IMM30_09 "绝缘测量电压_IMM30";
CM_ SG_ 2332114585 M2I_Byrack_Enable_IMM30_09 "绝缘采样使能位_IMM30";
CM_ SG_ 2332114585 M2I_Byrack_ReVeEnable_IMM30_09 "读取软件版本使能位_IMM30";
CM_ SG_ 2332114585 Reserved_09 "预留预留";
CM_ SG_ 2332114585 M2I_Byrack_IsPostTm_IMM30_09 "绝缘采样时间_IMM30";
CM_ SG_ 2332114585 M2I_Byrack_SysABStTm_IMM30_09 "电压稳定时间_IMM30";
CM_ SG_ 2332114586 CRC_M2I_Byrack_IMM30_10 "CRC校验_IMM30";
CM_ SG_ 2332114586 M2I_Byrack_HVS_IMM30_10 "绝缘测量电压_IMM30";
CM_ SG_ 2332114586 M2I_Byrack_Enable_IMM30_10 "绝缘采样使能位_IMM30";
CM_ SG_ 2332114586 M2I_Byrack_ReVeEnable_IMM30_10 "读取软件版本使能位_IMM30";
CM_ SG_ 2332114586 Reserved_10 "预留预留";
CM_ SG_ 2332114586 M2I_Byrack_IsPostTm_IMM30_10 "绝缘采样时间_IMM30";
CM_ SG_ 2332114586 M2I_Byrack_SysABStTm_IMM30_10 "电压稳定时间_IMM30";
CM_ SG_ 2332114587 CRC_M2I_Byrack_IMM30_11 "CRC校验_IMM30";
CM_ SG_ 2332114587 M2I_Byrack_HVS_IMM30_11 "绝缘测量电压_IMM30";
CM_ SG_ 2332114587 M2I_Byrack_Enable_IMM30_11 "绝缘采样使能位_IMM30";
CM_ SG_ 2332114587 M2I_Byrack_ReVeEnable_IMM30_11 "读取软件版本使能位_IMM30";
CM_ SG_ 2332114587 Reserved_11 "预留预留";
CM_ SG_ 2332114587 M2I_Byrack_IsPostTm_IMM30_11 "绝缘采样时间_IMM30";
CM_ SG_ 2332114587 M2I_Byrack_SysABStTm_IMM30_11 "电压稳定时间_IMM30";
CM_ SG_ 2332114588 CRC_M2I_Byrack_IMM30_12 "CRC校验_IMM30";
CM_ SG_ 2332114588 M2I_Byrack_HVS_IMM30_12 "绝缘测量电压_IMM30";
CM_ SG_ 2332114588 M2I_Byrack_Enable_IMM30_12 "绝缘采样使能位_IMM30";
CM_ SG_ 2332114588 M2I_Byrack_ReVeEnable_IMM30_12 "读取软件版本使能位_IMM30";
CM_ SG_ 2332114588 Reserved_12 "预留预留";
CM_ SG_ 2332114588 M2I_Byrack_IsPostTm_IMM30_12 "绝缘采样时间_IMM30";
CM_ SG_ 2332114588 M2I_Byrack_SysABStTm_IMM30_12 "电压稳定时间_IMM30";
CM_ SG_ 2332114589 CRC_M2I_Byrack_IMM30_13 "CRC校验_IMM30";
CM_ SG_ 2332114589 M2I_Byrack_HVS_IMM30_13 "绝缘测量电压_IMM30";
CM_ SG_ 2332114589 M2I_Byrack_Enable_IMM30_13 "绝缘采样使能位_IMM30";
CM_ SG_ 2332114589 M2I_Byrack_ReVeEnable_IMM30_13 "读取软件版本使能位_IMM30";
CM_ SG_ 2332114589 Reserved_13 "预留预留";
CM_ SG_ 2332114589 M2I_Byrack_IsPostTm_IMM30_13 "绝缘采样时间_IMM30";
CM_ SG_ 2332114589 M2I_Byrack_SysABStTm_IMM30_13 "电压稳定时间_IMM30";
CM_ SG_ 2332114590 CRC_M2I_Byrack_IMM30_14 "CRC校验_IMM30";
CM_ SG_ 2332114590 M2I_Byrack_HVS_IMM30_14 "绝缘测量电压_IMM30";
CM_ SG_ 2332114590 M2I_Byrack_Enable_IMM30_14 "绝缘采样使能位_IMM30";
CM_ SG_ 2332114590 M2I_Byrack_ReVeEnable_IMM30_14 "读取软件版本使能位_IMM30";
CM_ SG_ 2332114590 Reserved_14 "预留预留";
CM_ SG_ 2332114590 M2I_Byrack_IsPostTm_IMM30_14 "绝缘采样时间_IMM30";
CM_ SG_ 2332114590 M2I_Byrack_SysABStTm_IMM30_14 "电压稳定时间_IMM30";
CM_ SG_ 2332114591 CRC_M2I_Byrack_IMM30_15 "CRC校验_IMM30";
CM_ SG_ 2332114591 M2I_Byrack_HVS_IMM30_15 "绝缘测量电压_IMM30";
CM_ SG_ 2332114591 M2I_Byrack_Enable_IMM30_15 "绝缘采样使能位_IMM30";
CM_ SG_ 2332114591 M2I_Byrack_ReVeEnable_IMM30_15 "读取软件版本使能位_IMM30";
CM_ SG_ 2332114591 Reserved_15 "预留预留";
CM_ SG_ 2332114591 M2I_Byrack_IsPostTm_IMM30_15 "绝缘采样时间_IMM30";
CM_ SG_ 2332114591 M2I_Byrack_SysABStTm_IMM30_15 "电压稳定时间_IMM30";
CM_ SG_ 2332114592 CRC_M2I_Byrack_IMM30_16 "CRC校验_IMM30";
CM_ SG_ 2332114592 M2I_Byrack_HVS_IMM30_16 "绝缘测量电压_IMM30";
CM_ SG_ 2332114592 M2I_Byrack_Enable_IMM30_16 "绝缘采样使能位_IMM30";
CM_ SG_ 2332114592 M2I_Byrack_ReVeEnable_IMM30_16 "读取软件版本使能位_IMM30";
CM_ SG_ 2332114592 Reserved_16 "预留预留";
CM_ SG_ 2332114592 M2I_Byrack_IsPostTm_IMM30_16 "绝缘采样时间_IMM30";
CM_ SG_ 2332114592 M2I_Byrack_SysABStTm_IMM30_16 "电压稳定时间_IMM30";
CM_ SG_ 2332114593 CRC_M2I_Byrack_IMM30_17 "CRC校验_IMM30";
CM_ SG_ 2332114593 M2I_Byrack_HVS_IMM30_17 "绝缘测量电压_IMM30";
CM_ SG_ 2332114593 M2I_Byrack_Enable_IMM30_17 "绝缘采样使能位_IMM30";
CM_ SG_ 2332114593 M2I_Byrack_ReVeEnable_IMM30_17 "读取软件版本使能位_IMM30";
CM_ SG_ 2332114593 Reserved_17 "预留预留";
CM_ SG_ 2332114593 M2I_Byrack_IsPostTm_IMM30_17 "绝缘采样时间_IMM30";
CM_ SG_ 2332114593 M2I_Byrack_SysABStTm_IMM30_17 "电压稳定时间_IMM30";
CM_ SG_ 2332114594 CRC_M2I_Byrack_IMM30_18 "CRC校验_IMM30";
CM_ SG_ 2332114594 M2I_Byrack_HVS_IMM30_18 "绝缘测量电压_IMM30";
CM_ SG_ 2332114594 M2I_Byrack_Enable_IMM30_18 "绝缘采样使能位_IMM30";
CM_ SG_ 2332114594 M2I_Byrack_ReVeEnable_IMM30_18 "读取软件版本使能位_IMM30";
CM_ SG_ 2332114594 Reserved_18 "预留预留";
CM_ SG_ 2332114594 M2I_Byrack_IsPostTm_IMM30_18 "绝缘采样时间_IMM30";
CM_ SG_ 2332114594 M2I_Byrack_SysABStTm_IMM30_18 "电压稳定时间_IMM30";
CM_ SG_ 2332114595 CRC_M2I_Byrack_IMM30_19 "CRC校验_IMM30";
CM_ SG_ 2332114595 M2I_Byrack_HVS_IMM30_19 "绝缘测量电压_IMM30";
CM_ SG_ 2332114595 M2I_Byrack_Enable_IMM30_19 "绝缘采样使能位_IMM30";
CM_ SG_ 2332114595 M2I_Byrack_ReVeEnable_IMM30_19 "读取软件版本使能位_IMM30";
CM_ SG_ 2332114595 Reserved_19 "预留预留";
CM_ SG_ 2332114595 M2I_Byrack_IsPostTm_IMM30_19 "绝缘采样时间_IMM30";
CM_ SG_ 2332114595 M2I_Byrack_SysABStTm_IMM30_19 "电压稳定时间_IMM30";
CM_ SG_ 2332114596 CRC_M2I_Byrack_IMM30_20 "CRC校验_IMM30";
CM_ SG_ 2332114596 M2I_Byrack_HVS_IMM30_20 "绝缘测量电压_IMM30";
CM_ SG_ 2332114596 M2I_Byrack_Enable_IMM30_20 "绝缘采样使能位_IMM30";
CM_ SG_ 2332114596 M2I_Byrack_ReVeEnable_IMM30_20 "读取软件版本使能位_IMM30";
CM_ SG_ 2332114596 Reserved_20 "预留预留";
CM_ SG_ 2332114596 M2I_Byrack_IsPostTm_IMM30_20 "绝缘采样时间_IMM30";
CM_ SG_ 2332114596 M2I_Byrack_SysABStTm_IMM30_20 "电压稳定时间_IMM30";
CM_ SG_ 2332114597 CRC_M2I_Byrack_IMM30_21 "CRC校验_IMM30";
CM_ SG_ 2332114597 M2I_Byrack_HVS_IMM30_21 "绝缘测量电压_IMM30";
CM_ SG_ 2332114597 M2I_Byrack_Enable_IMM30_21 "绝缘采样使能位_IMM30";
CM_ SG_ 2332114597 M2I_Byrack_ReVeEnable_IMM30_21 "读取软件版本使能位_IMM30";
CM_ SG_ 2332114597 Reserved_21 "预留预留";
CM_ SG_ 2332114597 M2I_Byrack_IsPostTm_IMM30_21 "绝缘采样时间_IMM30";
CM_ SG_ 2332114597 M2I_Byrack_SysABStTm_IMM30_21 "电压稳定时间_IMM30";
CM_ SG_ 2332114598 CRC_M2I_Byrack_IMM30_22 "CRC校验_IMM30";
CM_ SG_ 2332114598 M2I_Byrack_HVS_IMM30_22 "绝缘测量电压_IMM30";
CM_ SG_ 2332114598 M2I_Byrack_Enable_IMM30_22 "绝缘采样使能位_IMM30";
CM_ SG_ 2332114598 M2I_Byrack_ReVeEnable_IMM30_22 "读取软件版本使能位_IMM30";
CM_ SG_ 2332114598 Reserved_22 "预留预留";
CM_ SG_ 2332114598 M2I_Byrack_IsPostTm_IMM30_22 "绝缘采样时间_IMM30";
CM_ SG_ 2332114598 M2I_Byrack_SysABStTm_IMM30_22 "电压稳定时间_IMM30";
CM_ SG_ 2332114599 CRC_M2I_Byrack_IMM30_23 "CRC校验_IMM30";
CM_ SG_ 2332114599 M2I_Byrack_HVS_IMM30_23 "绝缘测量电压_IMM30";
CM_ SG_ 2332114599 M2I_Byrack_Enable_IMM30_23 "绝缘采样使能位_IMM30";
CM_ SG_ 2332114599 M2I_Byrack_ReVeEnable_IMM30_23 "读取软件版本使能位_IMM30";
CM_ SG_ 2332114599 Reserved_23 "预留预留";
CM_ SG_ 2332114599 M2I_Byrack_IsPostTm_IMM30_23 "绝缘采样时间_IMM30";
CM_ SG_ 2332114599 M2I_Byrack_SysABStTm_IMM30_23 "电压稳定时间_IMM30";
CM_ SG_ 2332114600 CRC_M2I_Byrack_IMM30_24 "CRC校验_IMM30";
CM_ SG_ 2332114600 M2I_Byrack_HVS_IMM30_24 "绝缘测量电压_IMM30";
CM_ SG_ 2332114600 M2I_Byrack_Enable_IMM30_24 "绝缘采样使能位_IMM30";
CM_ SG_ 2332114600 M2I_Byrack_ReVeEnable_IMM30_24 "读取软件版本使能位_IMM30";
CM_ SG_ 2332114600 Reserved_24 "预留预留";
CM_ SG_ 2332114600 M2I_Byrack_IsPostTm_IMM30_24 "绝缘采样时间_IMM30";
CM_ SG_ 2332114600 M2I_Byrack_SysABStTm_IMM30_24 "电压稳定时间_IMM30";
CM_ SG_ 2332114601 CRC_M2I_Byrack_IMM30_25 "CRC校验_IMM30";
CM_ SG_ 2332114601 M2I_Byrack_HVS_IMM30_25 "绝缘测量电压_IMM30";
CM_ SG_ 2332114601 M2I_Byrack_Enable_IMM30_25 "绝缘采样使能位_IMM30";
CM_ SG_ 2332114601 M2I_Byrack_ReVeEnable_IMM30_25 "读取软件版本使能位_IMM30";
CM_ SG_ 2332114601 Reserved_25 "预留预留";
CM_ SG_ 2332114601 M2I_Byrack_IsPostTm_IMM30_25 "绝缘采样时间_IMM30";
CM_ SG_ 2332114601 M2I_Byrack_SysABStTm_IMM30_25 "电压稳定时间_IMM30";
CM_ SG_ 2332114602 CRC_M2I_Byrack_IMM30_26 "CRC校验_IMM30";
CM_ SG_ 2332114602 M2I_Byrack_HVS_IMM30_26 "绝缘测量电压_IMM30";
CM_ SG_ 2332114602 M2I_Byrack_Enable_IMM30_26 "绝缘采样使能位_IMM30";
CM_ SG_ 2332114602 M2I_Byrack_ReVeEnable_IMM30_26 "读取软件版本使能位_IMM30";
CM_ SG_ 2332114602 Reserved_26 "预留预留";
CM_ SG_ 2332114602 M2I_Byrack_IsPostTm_IMM30_26 "绝缘采样时间_IMM30";
CM_ SG_ 2332114602 M2I_Byrack_SysABStTm_IMM30_26 "电压稳定时间_IMM30";
CM_ SG_ 2332114603 CRC_M2I_Byrack_IMM30_27 "CRC校验_IMM30";
CM_ SG_ 2332114603 M2I_Byrack_HVS_IMM30_27 "绝缘测量电压_IMM30";
CM_ SG_ 2332114603 M2I_Byrack_Enable_IMM30_27 "绝缘采样使能位_IMM30";
CM_ SG_ 2332114603 M2I_Byrack_ReVeEnable_IMM30_27 "读取软件版本使能位_IMM30";
CM_ SG_ 2332114603 Reserved_27 "预留预留";
CM_ SG_ 2332114603 M2I_Byrack_IsPostTm_IMM30_27 "绝缘采样时间_IMM30";
CM_ SG_ 2332114603 M2I_Byrack_SysABStTm_IMM30_27 "电压稳定时间_IMM30";
CM_ SG_ 2332114604 CRC_M2I_Byrack_IMM30_28 "CRC校验_IMM30";
CM_ SG_ 2332114604 M2I_Byrack_HVS_IMM30_28 "绝缘测量电压_IMM30";
CM_ SG_ 2332114604 M2I_Byrack_Enable_IMM30_28 "绝缘采样使能位_IMM30";
CM_ SG_ 2332114604 M2I_Byrack_ReVeEnable_IMM30_28 "读取软件版本使能位_IMM30";
CM_ SG_ 2332114604 Reserved_28 "预留预留";
CM_ SG_ 2332114604 M2I_Byrack_IsPostTm_IMM30_28 "绝缘采样时间_IMM30";
CM_ SG_ 2332114604 M2I_Byrack_SysABStTm_IMM30_28 "电压稳定时间_IMM30";
CM_ SG_ 2332114605 CRC_M2I_Byrack_IMM30_29 "CRC校验_IMM30";
CM_ SG_ 2332114605 M2I_Byrack_HVS_IMM30_29 "绝缘测量电压_IMM30";
CM_ SG_ 2332114605 M2I_Byrack_Enable_IMM30_29 "绝缘采样使能位_IMM30";
CM_ SG_ 2332114605 M2I_Byrack_ReVeEnable_IMM30_29 "读取软件版本使能位_IMM30";
CM_ SG_ 2332114605 Reserved_29 "预留预留";
CM_ SG_ 2332114605 M2I_Byrack_IsPostTm_IMM30_29 "绝缘采样时间_IMM30";
CM_ SG_ 2332114605 M2I_Byrack_SysABStTm_IMM30_29 "电压稳定时间_IMM30";
CM_ SG_ 2332114606 CRC_M2I_Byrack_IMM30_30 "CRC校验_IMM30";
CM_ SG_ 2332114606 M2I_Byrack_HVS_IMM30_30 "绝缘测量电压_IMM30";
CM_ SG_ 2332114606 M2I_Byrack_Enable_IMM30_30 "绝缘采样使能位_IMM30";
CM_ SG_ 2332114606 M2I_Byrack_ReVeEnable_IMM30_30 "读取软件版本使能位_IMM30";
CM_ SG_ 2332114606 Reserved_30 "预留预留";
CM_ SG_ 2332114606 M2I_Byrack_IsPostTm_IMM30_30 "绝缘采样时间_IMM30";
CM_ SG_ 2332114606 M2I_Byrack_SysABStTm_IMM30_30 "电压稳定时间_IMM30";
CM_ SG_ 2332114607 CRC_M2I_Byrack_IMM30_31 "CRC校验_IMM30";
CM_ SG_ 2332114607 M2I_Byrack_HVS_IMM30_31 "绝缘测量电压_IMM30";
CM_ SG_ 2332114607 M2I_Byrack_Enable_IMM30_31 "绝缘采样使能位_IMM30";
CM_ SG_ 2332114607 M2I_Byrack_ReVeEnable_IMM30_31 "读取软件版本使能位_IMM30";
CM_ SG_ 2332114607 Reserved_31 "预留预留";
CM_ SG_ 2332114607 M2I_Byrack_IsPostTm_IMM30_31 "绝缘采样时间_IMM30";
CM_ SG_ 2332114607 M2I_Byrack_SysABStTm_IMM30_31 "电压稳定时间_IMM30";
CM_ SG_ 2332114833 CRC_M2I_Byrack_IMM31_01 "CRC校验_IMM31";
CM_ SG_ 2332114833 M2I_Byrack_HVS_IMM31_01 "绝缘测量电压_IMM31";
CM_ SG_ 2332114833 M2I_Byrack_Enable_IMM31_01 "绝缘采样使能位_IMM31";
CM_ SG_ 2332114833 M2I_Byrack_ReVeEnable_IMM31_01 "读取软件版本使能位_IMM31";
CM_ SG_ 2332114833 Reserved_01 "预留预留";
CM_ SG_ 2332114833 M2I_Byrack_IsPostTm_IMM31_01 "绝缘采样时间_IMM31";
CM_ SG_ 2332114833 M2I_Byrack_SysABStTm_IMM31_01 "电压稳定时间_IMM31";
CM_ SG_ 2332114834 CRC_M2I_Byrack_IMM31_02 "CRC校验_IMM31";
CM_ SG_ 2332114834 M2I_Byrack_HVS_IMM31_02 "绝缘测量电压_IMM31";
CM_ SG_ 2332114834 M2I_Byrack_Enable_IMM31_02 "绝缘采样使能位_IMM31";
CM_ SG_ 2332114834 M2I_Byrack_ReVeEnable_IMM31_02 "读取软件版本使能位_IMM31";
CM_ SG_ 2332114834 Reserved_02 "预留预留";
CM_ SG_ 2332114834 M2I_Byrack_IsPostTm_IMM31_02 "绝缘采样时间_IMM31";
CM_ SG_ 2332114834 M2I_Byrack_SysABStTm_IMM31_02 "电压稳定时间_IMM31";
CM_ SG_ 2332114835 CRC_M2I_Byrack_IMM31_03 "CRC校验_IMM31";
CM_ SG_ 2332114835 M2I_Byrack_HVS_IMM31_03 "绝缘测量电压_IMM31";
CM_ SG_ 2332114835 M2I_Byrack_Enable_IMM31_03 "绝缘采样使能位_IMM31";
CM_ SG_ 2332114835 M2I_Byrack_ReVeEnable_IMM31_03 "读取软件版本使能位_IMM31";
CM_ SG_ 2332114835 Reserved_03 "预留预留";
CM_ SG_ 2332114835 M2I_Byrack_IsPostTm_IMM31_03 "绝缘采样时间_IMM31";
CM_ SG_ 2332114835 M2I_Byrack_SysABStTm_IMM31_03 "电压稳定时间_IMM31";
CM_ SG_ 2332114836 CRC_M2I_Byrack_IMM31_04 "CRC校验_IMM31";
CM_ SG_ 2332114836 M2I_Byrack_HVS_IMM31_04 "绝缘测量电压_IMM31";
CM_ SG_ 2332114836 M2I_Byrack_Enable_IMM31_04 "绝缘采样使能位_IMM31";
CM_ SG_ 2332114836 M2I_Byrack_ReVeEnable_IMM31_04 "读取软件版本使能位_IMM31";
CM_ SG_ 2332114836 Reserved_04 "预留预留";
CM_ SG_ 2332114836 M2I_Byrack_IsPostTm_IMM31_04 "绝缘采样时间_IMM31";
CM_ SG_ 2332114836 M2I_Byrack_SysABStTm_IMM31_04 "电压稳定时间_IMM31";
CM_ SG_ 2332114837 CRC_M2I_Byrack_IMM31_05 "CRC校验_IMM31";
CM_ SG_ 2332114837 M2I_Byrack_HVS_IMM31_05 "绝缘测量电压_IMM31";
CM_ SG_ 2332114837 M2I_Byrack_Enable_IMM31_05 "绝缘采样使能位_IMM31";
CM_ SG_ 2332114837 M2I_Byrack_ReVeEnable_IMM31_05 "读取软件版本使能位_IMM31";
CM_ SG_ 2332114837 Reserved_05 "预留预留";
CM_ SG_ 2332114837 M2I_Byrack_IsPostTm_IMM31_05 "绝缘采样时间_IMM31";
CM_ SG_ 2332114837 M2I_Byrack_SysABStTm_IMM31_05 "电压稳定时间_IMM31";
CM_ SG_ 2332114838 CRC_M2I_Byrack_IMM31_06 "CRC校验_IMM31";
CM_ SG_ 2332114838 M2I_Byrack_HVS_IMM31_06 "绝缘测量电压_IMM31";
CM_ SG_ 2332114838 M2I_Byrack_Enable_IMM31_06 "绝缘采样使能位_IMM31";
CM_ SG_ 2332114838 M2I_Byrack_ReVeEnable_IMM31_06 "读取软件版本使能位_IMM31";
CM_ SG_ 2332114838 Reserved_06 "预留预留";
CM_ SG_ 2332114838 M2I_Byrack_IsPostTm_IMM31_06 "绝缘采样时间_IMM31";
CM_ SG_ 2332114838 M2I_Byrack_SysABStTm_IMM31_06 "电压稳定时间_IMM31";
CM_ SG_ 2332114839 CRC_M2I_Byrack_IMM31_07 "CRC校验_IMM31";
CM_ SG_ 2332114839 M2I_Byrack_HVS_IMM31_07 "绝缘测量电压_IMM31";
CM_ SG_ 2332114839 M2I_Byrack_Enable_IMM31_07 "绝缘采样使能位_IMM31";
CM_ SG_ 2332114839 M2I_Byrack_ReVeEnable_IMM31_07 "读取软件版本使能位_IMM31";
CM_ SG_ 2332114839 Reserved_07 "预留预留";
CM_ SG_ 2332114839 M2I_Byrack_IsPostTm_IMM31_07 "绝缘采样时间_IMM31";
CM_ SG_ 2332114839 M2I_Byrack_SysABStTm_IMM31_07 "电压稳定时间_IMM31";
CM_ SG_ 2332114840 CRC_M2I_Byrack_IMM31_08 "CRC校验_IMM31";
CM_ SG_ 2332114840 M2I_Byrack_HVS_IMM31_08 "绝缘测量电压_IMM31";
CM_ SG_ 2332114840 M2I_Byrack_Enable_IMM31_08 "绝缘采样使能位_IMM31";
CM_ SG_ 2332114840 M2I_Byrack_ReVeEnable_IMM31_08 "读取软件版本使能位_IMM31";
CM_ SG_ 2332114840 Reserved_08 "预留预留";
CM_ SG_ 2332114840 M2I_Byrack_IsPostTm_IMM31_08 "绝缘采样时间_IMM31";
CM_ SG_ 2332114840 M2I_Byrack_SysABStTm_IMM31_08 "电压稳定时间_IMM31";
CM_ SG_ 2332114841 CRC_M2I_Byrack_IMM31_09 "CRC校验_IMM31";
CM_ SG_ 2332114841 M2I_Byrack_HVS_IMM31_09 "绝缘测量电压_IMM31";
CM_ SG_ 2332114841 M2I_Byrack_Enable_IMM31_09 "绝缘采样使能位_IMM31";
CM_ SG_ 2332114841 M2I_Byrack_ReVeEnable_IMM31_09 "读取软件版本使能位_IMM31";
CM_ SG_ 2332114841 Reserved_09 "预留预留";
CM_ SG_ 2332114841 M2I_Byrack_IsPostTm_IMM31_09 "绝缘采样时间_IMM31";
CM_ SG_ 2332114841 M2I_Byrack_SysABStTm_IMM31_09 "电压稳定时间_IMM31";
CM_ SG_ 2332114842 CRC_M2I_Byrack_IMM31_10 "CRC校验_IMM31";
CM_ SG_ 2332114842 M2I_Byrack_HVS_IMM31_10 "绝缘测量电压_IMM31";
CM_ SG_ 2332114842 M2I_Byrack_Enable_IMM31_10 "绝缘采样使能位_IMM31";
CM_ SG_ 2332114842 M2I_Byrack_ReVeEnable_IMM31_10 "读取软件版本使能位_IMM31";
CM_ SG_ 2332114842 Reserved_10 "预留预留";
CM_ SG_ 2332114842 M2I_Byrack_IsPostTm_IMM31_10 "绝缘采样时间_IMM31";
CM_ SG_ 2332114842 M2I_Byrack_SysABStTm_IMM31_10 "电压稳定时间_IMM31";
CM_ SG_ 2332114843 CRC_M2I_Byrack_IMM31_11 "CRC校验_IMM31";
CM_ SG_ 2332114843 M2I_Byrack_HVS_IMM31_11 "绝缘测量电压_IMM31";
CM_ SG_ 2332114843 M2I_Byrack_Enable_IMM31_11 "绝缘采样使能位_IMM31";
CM_ SG_ 2332114843 M2I_Byrack_ReVeEnable_IMM31_11 "读取软件版本使能位_IMM31";
CM_ SG_ 2332114843 Reserved_11 "预留预留";
CM_ SG_ 2332114843 M2I_Byrack_IsPostTm_IMM31_11 "绝缘采样时间_IMM31";
CM_ SG_ 2332114843 M2I_Byrack_SysABStTm_IMM31_11 "电压稳定时间_IMM31";
CM_ SG_ 2332114844 CRC_M2I_Byrack_IMM31_12 "CRC校验_IMM31";
CM_ SG_ 2332114844 M2I_Byrack_HVS_IMM31_12 "绝缘测量电压_IMM31";
CM_ SG_ 2332114844 M2I_Byrack_Enable_IMM31_12 "绝缘采样使能位_IMM31";
CM_ SG_ 2332114844 M2I_Byrack_ReVeEnable_IMM31_12 "读取软件版本使能位_IMM31";
CM_ SG_ 2332114844 Reserved_12 "预留预留";
CM_ SG_ 2332114844 M2I_Byrack_IsPostTm_IMM31_12 "绝缘采样时间_IMM31";
CM_ SG_ 2332114844 M2I_Byrack_SysABStTm_IMM31_12 "电压稳定时间_IMM31";
CM_ SG_ 2332114845 CRC_M2I_Byrack_IMM31_13 "CRC校验_IMM31";
CM_ SG_ 2332114845 M2I_Byrack_HVS_IMM31_13 "绝缘测量电压_IMM31";
CM_ SG_ 2332114845 M2I_Byrack_Enable_IMM31_13 "绝缘采样使能位_IMM31";
CM_ SG_ 2332114845 M2I_Byrack_ReVeEnable_IMM31_13 "读取软件版本使能位_IMM31";
CM_ SG_ 2332114845 Reserved_13 "预留预留";
CM_ SG_ 2332114845 M2I_Byrack_IsPostTm_IMM31_13 "绝缘采样时间_IMM31";
CM_ SG_ 2332114845 M2I_Byrack_SysABStTm_IMM31_13 "电压稳定时间_IMM31";
CM_ SG_ 2332114846 CRC_M2I_Byrack_IMM31_14 "CRC校验_IMM31";
CM_ SG_ 2332114846 M2I_Byrack_HVS_IMM31_14 "绝缘测量电压_IMM31";
CM_ SG_ 2332114846 M2I_Byrack_Enable_IMM31_14 "绝缘采样使能位_IMM31";
CM_ SG_ 2332114846 M2I_Byrack_ReVeEnable_IMM31_14 "读取软件版本使能位_IMM31";
CM_ SG_ 2332114846 Reserved_14 "预留预留";
CM_ SG_ 2332114846 M2I_Byrack_IsPostTm_IMM31_14 "绝缘采样时间_IMM31";
CM_ SG_ 2332114846 M2I_Byrack_SysABStTm_IMM31_14 "电压稳定时间_IMM31";
CM_ SG_ 2332114847 CRC_M2I_Byrack_IMM31_15 "CRC校验_IMM31";
CM_ SG_ 2332114847 M2I_Byrack_HVS_IMM31_15 "绝缘测量电压_IMM31";
CM_ SG_ 2332114847 M2I_Byrack_Enable_IMM31_15 "绝缘采样使能位_IMM31";
CM_ SG_ 2332114847 M2I_Byrack_ReVeEnable_IMM31_15 "读取软件版本使能位_IMM31";
CM_ SG_ 2332114847 Reserved_15 "预留预留";
CM_ SG_ 2332114847 M2I_Byrack_IsPostTm_IMM31_15 "绝缘采样时间_IMM31";
CM_ SG_ 2332114847 M2I_Byrack_SysABStTm_IMM31_15 "电压稳定时间_IMM31";
CM_ SG_ 2332114848 CRC_M2I_Byrack_IMM31_16 "CRC校验_IMM31";
CM_ SG_ 2332114848 M2I_Byrack_HVS_IMM31_16 "绝缘测量电压_IMM31";
CM_ SG_ 2332114848 M2I_Byrack_Enable_IMM31_16 "绝缘采样使能位_IMM31";
CM_ SG_ 2332114848 M2I_Byrack_ReVeEnable_IMM31_16 "读取软件版本使能位_IMM31";
CM_ SG_ 2332114848 Reserved_16 "预留预留";
CM_ SG_ 2332114848 M2I_Byrack_IsPostTm_IMM31_16 "绝缘采样时间_IMM31";
CM_ SG_ 2332114848 M2I_Byrack_SysABStTm_IMM31_16 "电压稳定时间_IMM31";
CM_ SG_ 2332114849 CRC_M2I_Byrack_IMM31_17 "CRC校验_IMM31";
CM_ SG_ 2332114849 M2I_Byrack_HVS_IMM31_17 "绝缘测量电压_IMM31";
CM_ SG_ 2332114849 M2I_Byrack_Enable_IMM31_17 "绝缘采样使能位_IMM31";
CM_ SG_ 2332114849 M2I_Byrack_ReVeEnable_IMM31_17 "读取软件版本使能位_IMM31";
CM_ SG_ 2332114849 Reserved_17 "预留预留";
CM_ SG_ 2332114849 M2I_Byrack_IsPostTm_IMM31_17 "绝缘采样时间_IMM31";
CM_ SG_ 2332114849 M2I_Byrack_SysABStTm_IMM31_17 "电压稳定时间_IMM31";
CM_ SG_ 2332114850 CRC_M2I_Byrack_IMM31_18 "CRC校验_IMM31";
CM_ SG_ 2332114850 M2I_Byrack_HVS_IMM31_18 "绝缘测量电压_IMM31";
CM_ SG_ 2332114850 M2I_Byrack_Enable_IMM31_18 "绝缘采样使能位_IMM31";
CM_ SG_ 2332114850 M2I_Byrack_ReVeEnable_IMM31_18 "读取软件版本使能位_IMM31";
CM_ SG_ 2332114850 Reserved_18 "预留预留";
CM_ SG_ 2332114850 M2I_Byrack_IsPostTm_IMM31_18 "绝缘采样时间_IMM31";
CM_ SG_ 2332114850 M2I_Byrack_SysABStTm_IMM31_18 "电压稳定时间_IMM31";
CM_ SG_ 2332114851 CRC_M2I_Byrack_IMM31_19 "CRC校验_IMM31";
CM_ SG_ 2332114851 M2I_Byrack_HVS_IMM31_19 "绝缘测量电压_IMM31";
CM_ SG_ 2332114851 M2I_Byrack_Enable_IMM31_19 "绝缘采样使能位_IMM31";
CM_ SG_ 2332114851 M2I_Byrack_ReVeEnable_IMM31_19 "读取软件版本使能位_IMM31";
CM_ SG_ 2332114851 Reserved_19 "预留预留";
CM_ SG_ 2332114851 M2I_Byrack_IsPostTm_IMM31_19 "绝缘采样时间_IMM31";
CM_ SG_ 2332114851 M2I_Byrack_SysABStTm_IMM31_19 "电压稳定时间_IMM31";
CM_ SG_ 2332114852 CRC_M2I_Byrack_IMM31_20 "CRC校验_IMM31";
CM_ SG_ 2332114852 M2I_Byrack_HVS_IMM31_20 "绝缘测量电压_IMM31";
CM_ SG_ 2332114852 M2I_Byrack_Enable_IMM31_20 "绝缘采样使能位_IMM31";
CM_ SG_ 2332114852 M2I_Byrack_ReVeEnable_IMM31_20 "读取软件版本使能位_IMM31";
CM_ SG_ 2332114852 Reserved_20 "预留预留";
CM_ SG_ 2332114852 M2I_Byrack_IsPostTm_IMM31_20 "绝缘采样时间_IMM31";
CM_ SG_ 2332114852 M2I_Byrack_SysABStTm_IMM31_20 "电压稳定时间_IMM31";
CM_ SG_ 2332114853 CRC_M2I_Byrack_IMM31_21 "CRC校验_IMM31";
CM_ SG_ 2332114853 M2I_Byrack_HVS_IMM31_21 "绝缘测量电压_IMM31";
CM_ SG_ 2332114853 M2I_Byrack_Enable_IMM31_21 "绝缘采样使能位_IMM31";
CM_ SG_ 2332114853 M2I_Byrack_ReVeEnable_IMM31_21 "读取软件版本使能位_IMM31";
CM_ SG_ 2332114853 Reserved_21 "预留预留";
CM_ SG_ 2332114853 M2I_Byrack_IsPostTm_IMM31_21 "绝缘采样时间_IMM31";
CM_ SG_ 2332114853 M2I_Byrack_SysABStTm_IMM31_21 "电压稳定时间_IMM31";
CM_ SG_ 2332114854 CRC_M2I_Byrack_IMM31_22 "CRC校验_IMM31";
CM_ SG_ 2332114854 M2I_Byrack_HVS_IMM31_22 "绝缘测量电压_IMM31";
CM_ SG_ 2332114854 M2I_Byrack_Enable_IMM31_22 "绝缘采样使能位_IMM31";
CM_ SG_ 2332114854 M2I_Byrack_ReVeEnable_IMM31_22 "读取软件版本使能位_IMM31";
CM_ SG_ 2332114854 Reserved_22 "预留预留";
CM_ SG_ 2332114854 M2I_Byrack_IsPostTm_IMM31_22 "绝缘采样时间_IMM31";
CM_ SG_ 2332114854 M2I_Byrack_SysABStTm_IMM31_22 "电压稳定时间_IMM31";
CM_ SG_ 2332114855 CRC_M2I_Byrack_IMM31_23 "CRC校验_IMM31";
CM_ SG_ 2332114855 M2I_Byrack_HVS_IMM31_23 "绝缘测量电压_IMM31";
CM_ SG_ 2332114855 M2I_Byrack_Enable_IMM31_23 "绝缘采样使能位_IMM31";
CM_ SG_ 2332114855 M2I_Byrack_ReVeEnable_IMM31_23 "读取软件版本使能位_IMM31";
CM_ SG_ 2332114855 Reserved_23 "预留预留";
CM_ SG_ 2332114855 M2I_Byrack_IsPostTm_IMM31_23 "绝缘采样时间_IMM31";
CM_ SG_ 2332114855 M2I_Byrack_SysABStTm_IMM31_23 "电压稳定时间_IMM31";
CM_ SG_ 2332114856 CRC_M2I_Byrack_IMM31_24 "CRC校验_IMM31";
CM_ SG_ 2332114856 M2I_Byrack_HVS_IMM31_24 "绝缘测量电压_IMM31";
CM_ SG_ 2332114856 M2I_Byrack_Enable_IMM31_24 "绝缘采样使能位_IMM31";
CM_ SG_ 2332114856 M2I_Byrack_ReVeEnable_IMM31_24 "读取软件版本使能位_IMM31";
CM_ SG_ 2332114856 Reserved_24 "预留预留";
CM_ SG_ 2332114856 M2I_Byrack_IsPostTm_IMM31_24 "绝缘采样时间_IMM31";
CM_ SG_ 2332114856 M2I_Byrack_SysABStTm_IMM31_24 "电压稳定时间_IMM31";
CM_ SG_ 2332114857 CRC_M2I_Byrack_IMM31_25 "CRC校验_IMM31";
CM_ SG_ 2332114857 M2I_Byrack_HVS_IMM31_25 "绝缘测量电压_IMM31";
CM_ SG_ 2332114857 M2I_Byrack_Enable_IMM31_25 "绝缘采样使能位_IMM31";
CM_ SG_ 2332114857 M2I_Byrack_ReVeEnable_IMM31_25 "读取软件版本使能位_IMM31";
CM_ SG_ 2332114857 Reserved_25 "预留预留";
CM_ SG_ 2332114857 M2I_Byrack_IsPostTm_IMM31_25 "绝缘采样时间_IMM31";
CM_ SG_ 2332114857 M2I_Byrack_SysABStTm_IMM31_25 "电压稳定时间_IMM31";
CM_ SG_ 2332114858 CRC_M2I_Byrack_IMM31_26 "CRC校验_IMM31";
CM_ SG_ 2332114858 M2I_Byrack_HVS_IMM31_26 "绝缘测量电压_IMM31";
CM_ SG_ 2332114858 M2I_Byrack_Enable_IMM31_26 "绝缘采样使能位_IMM31";
CM_ SG_ 2332114858 M2I_Byrack_ReVeEnable_IMM31_26 "读取软件版本使能位_IMM31";
CM_ SG_ 2332114858 Reserved_26 "预留预留";
CM_ SG_ 2332114858 M2I_Byrack_IsPostTm_IMM31_26 "绝缘采样时间_IMM31";
CM_ SG_ 2332114858 M2I_Byrack_SysABStTm_IMM31_26 "电压稳定时间_IMM31";
CM_ SG_ 2332114859 CRC_M2I_Byrack_IMM31_27 "CRC校验_IMM31";
CM_ SG_ 2332114859 M2I_Byrack_HVS_IMM31_27 "绝缘测量电压_IMM31";
CM_ SG_ 2332114859 M2I_Byrack_Enable_IMM31_27 "绝缘采样使能位_IMM31";
CM_ SG_ 2332114859 M2I_Byrack_ReVeEnable_IMM31_27 "读取软件版本使能位_IMM31";
CM_ SG_ 2332114859 Reserved_27 "预留预留";
CM_ SG_ 2332114859 M2I_Byrack_IsPostTm_IMM31_27 "绝缘采样时间_IMM31";
CM_ SG_ 2332114859 M2I_Byrack_SysABStTm_IMM31_27 "电压稳定时间_IMM31";
CM_ SG_ 2332114860 CRC_M2I_Byrack_IMM31_28 "CRC校验_IMM31";
CM_ SG_ 2332114860 M2I_Byrack_HVS_IMM31_28 "绝缘测量电压_IMM31";
CM_ SG_ 2332114860 M2I_Byrack_Enable_IMM31_28 "绝缘采样使能位_IMM31";
CM_ SG_ 2332114860 M2I_Byrack_ReVeEnable_IMM31_28 "读取软件版本使能位_IMM31";
CM_ SG_ 2332114860 Reserved_28 "预留预留";
CM_ SG_ 2332114860 M2I_Byrack_IsPostTm_IMM31_28 "绝缘采样时间_IMM31";
CM_ SG_ 2332114860 M2I_Byrack_SysABStTm_IMM31_28 "电压稳定时间_IMM31";
CM_ SG_ 2332114861 CRC_M2I_Byrack_IMM31_29 "CRC校验_IMM31";
CM_ SG_ 2332114861 M2I_Byrack_HVS_IMM31_29 "绝缘测量电压_IMM31";
CM_ SG_ 2332114861 M2I_Byrack_Enable_IMM31_29 "绝缘采样使能位_IMM31";
CM_ SG_ 2332114861 M2I_Byrack_ReVeEnable_IMM31_29 "读取软件版本使能位_IMM31";
CM_ SG_ 2332114861 Reserved_29 "预留预留";
CM_ SG_ 2332114861 M2I_Byrack_IsPostTm_IMM31_29 "绝缘采样时间_IMM31";
CM_ SG_ 2332114861 M2I_Byrack_SysABStTm_IMM31_29 "电压稳定时间_IMM31";
CM_ SG_ 2332114862 CRC_M2I_Byrack_IMM31_30 "CRC校验_IMM31";
CM_ SG_ 2332114862 M2I_Byrack_HVS_IMM31_30 "绝缘测量电压_IMM31";
CM_ SG_ 2332114862 M2I_Byrack_Enable_IMM31_30 "绝缘采样使能位_IMM31";
CM_ SG_ 2332114862 M2I_Byrack_ReVeEnable_IMM31_30 "读取软件版本使能位_IMM31";
CM_ SG_ 2332114862 Reserved_30 "预留预留";
CM_ SG_ 2332114862 M2I_Byrack_IsPostTm_IMM31_30 "绝缘采样时间_IMM31";
CM_ SG_ 2332114862 M2I_Byrack_SysABStTm_IMM31_30 "电压稳定时间_IMM31";
CM_ SG_ 2332114863 CRC_M2I_Byrack_IMM31_31 "CRC校验_IMM31";
CM_ SG_ 2332114863 M2I_Byrack_HVS_IMM31_31 "绝缘测量电压_IMM31";
CM_ SG_ 2332114863 M2I_Byrack_Enable_IMM31_31 "绝缘采样使能位_IMM31";
CM_ SG_ 2332114863 M2I_Byrack_ReVeEnable_IMM31_31 "读取软件版本使能位_IMM31";
CM_ SG_ 2332114863 Reserved_31 "预留预留";
CM_ SG_ 2332114863 M2I_Byrack_IsPostTm_IMM31_31 "绝缘采样时间_IMM31";
CM_ SG_ 2332114863 M2I_Byrack_SysABStTm_IMM31_31 "电压稳定时间_IMM31";
CM_ SG_ 2332946065 Reserved_01 "预留";
CM_ SG_ 2332946066 Reserved_02 "预留";
CM_ SG_ 2332946067 Reserved_03 "预留";
CM_ SG_ 2332946068 Reserved_04 "预留";
CM_ SG_ 2332946069 Reserved_05 "预留";
CM_ SG_ 2332946070 Reserved_06 "预留";
CM_ SG_ 2332946071 Reserved_07 "预留";
CM_ SG_ 2332946072 Reserved_08 "预留";
CM_ SG_ 2332946073 Reserved_09 "预留";
CM_ SG_ 2332946074 Reserved_10 "预留";
CM_ SG_ 2332946075 Reserved_11 "预留";
CM_ SG_ 2332946076 Reserved_12 "预留";
CM_ SG_ 2332946077 Reserved_13 "预留";
CM_ SG_ 2332946078 Reserved_14 "预留";
CM_ SG_ 2332946079 Reserved_15 "预留";
CM_ SG_ 2332946080 Reserved_16 "预留";
CM_ SG_ 2332946081 Reserved_17 "预留";
CM_ SG_ 2332946082 Reserved_18 "预留";
CM_ SG_ 2332946083 Reserved_19 "预留";
CM_ SG_ 2332946084 Reserved_20 "预留";
CM_ SG_ 2332946085 Reserved_21 "预留";
CM_ SG_ 2332946086 Reserved_22 "预留";
CM_ SG_ 2332946087 Reserved_23 "预留";
CM_ SG_ 2332946088 Reserved_24 "预留";
CM_ SG_ 2332946089 Reserved_25 "预留";
CM_ SG_ 2332946090 Reserved_26 "预留";
CM_ SG_ 2332946091 Reserved_27 "预留";
CM_ SG_ 2332946092 Reserved_28 "预留";
CM_ SG_ 2332946093 Reserved_29 "预留";
CM_ SG_ 2332946094 Reserved_30 "预留";
CM_ SG_ 2332946095 Reserved_31 "预留";
CM_ SG_ 2333077137 Reserved_01 "预留";
CM_ SG_ 2333077138 Reserved_02 "预留";
CM_ SG_ 2333077139 Reserved_03 "预留";
CM_ SG_ 2333077140 Reserved_04 "预留";
CM_ SG_ 2333077141 Reserved_05 "预留";
CM_ SG_ 2333077142 Reserved_06 "预留";
CM_ SG_ 2333077143 Reserved_07 "预留";
CM_ SG_ 2333077144 Reserved_08 "预留";
CM_ SG_ 2333077145 Reserved_09 "预留";
CM_ SG_ 2333077146 Reserved_10 "预留";
CM_ SG_ 2333077147 Reserved_11 "预留";
VAL_ 2332113579 M2I_Byrack_Enable_IMM26_27 1 "Deactive" 2 "Active" ;
VAL_ 2332113579 M2I_Byrack_ReVeEnable_IMM26_27 0 "invalid" 1 "Read SW-Version" 2 "Read HW-Version" 3 "Barcode" ;
VAL_ 2332113580 M2I_Byrack_Enable_IMM26_28 1 "Deactive" 2 "Active" ;
VAL_ 2332113580 M2I_Byrack_ReVeEnable_IMM26_28 0 "invalid" 1 "Read SW-Version" 2 "Read HW-Version" 3 "Barcode" ;
VAL_ 2332113581 M2I_Byrack_Enable_IMM26_29 1 "Deactive" 2 "Active" ;
VAL_ 2332113581 M2I_Byrack_ReVeEnable_IMM26_29 0 "invalid" 1 "Read SW-Version" 2 "Read HW-Version" 3 "Barcode" ;
VAL_ 2332113582 M2I_Byrack_Enable_IMM26_30 1 "Deactive" 2 "Active" ;
VAL_ 2332113582 M2I_Byrack_ReVeEnable_IMM26_30 0 "invalid" 1 "Read SW-Version" 2 "Read HW-Version" 3 "Barcode" ;
VAL_ 2332113583 M2I_Byrack_Enable_IMM26_31 1 "Deactive" 2 "Active" ;
VAL_ 2332113583 M2I_Byrack_ReVeEnable_IMM26_31 0 "invalid" 1 "Read SW-Version" 2 "Read HW-Version" 3 "Barcode" ;
VAL_ 2332113809 M2I_Byrack_Enable_IMM27_01 1 "Deactive" 2 "Active" ;
VAL_ 2332113809 M2I_Byrack_ReVeEnable_IMM27_01 0 "invalid" 1 "Read SW-Version" 2 "Read HW-Version" 3 "Barcode" ;
VAL_ 2332113810 M2I_Byrack_Enable_IMM27_02 1 "Deactive" 2 "Active" ;
VAL_ 2332113810 M2I_Byrack_ReVeEnable_IMM27_02 0 "invalid" 1 "Read SW-Version" 2 "Read HW-Version" 3 "Barcode" ;
VAL_ 2332113811 M2I_Byrack_Enable_IMM27_03 1 "Deactive" 2 "Active" ;
VAL_ 2332113811 M2I_Byrack_ReVeEnable_IMM27_03 0 "invalid" 1 "Read SW-Version" 2 "Read HW-Version" 3 "Barcode" ;
VAL_ 2332113812 M2I_Byrack_Enable_IMM27_04 1 "Deactive" 2 "Active" ;
VAL_ 2332113812 M2I_Byrack_ReVeEnable_IMM27_04 0 "invalid" 1 "Read SW-Version" 2 "Read HW-Version" 3 "Barcode" ;
VAL_ 2332113813 M2I_Byrack_Enable_IMM27_05 1 "Deactive" 2 "Active" ;
VAL_ 2332113813 M2I_Byrack_ReVeEnable_IMM27_05 0 "invalid" 1 "Read SW-Version" 2 "Read HW-Version" 3 "Barcode" ;
VAL_ 2332113814 M2I_Byrack_Enable_IMM27_06 1 "Deactive" 2 "Active" ;
VAL_ 2332113814 M2I_Byrack_ReVeEnable_IMM27_06 0 "invalid" 1 "Read SW-Version" 2 "Read HW-Version" 3 "Barcode" ;
VAL_ 2332113815 M2I_Byrack_Enable_IMM27_07 1 "Deactive" 2 "Active" ;
VAL_ 2332113815 M2I_Byrack_ReVeEnable_IMM27_07 0 "invalid" 1 "Read SW-Version" 2 "Read HW-Version" 3 "Barcode" ;
VAL_ 2332113816 M2I_Byrack_Enable_IMM27_08 1 "Deactive" 2 "Active" ;
VAL_ 2332113816 M2I_Byrack_ReVeEnable_IMM27_08 0 "invalid" 1 "Read SW-Version" 2 "Read HW-Version" 3 "Barcode" ;
VAL_ 2332113817 M2I_Byrack_Enable_IMM27_09 1 "Deactive" 2 "Active" ;
VAL_ 2332113817 M2I_Byrack_ReVeEnable_IMM27_09 0 "invalid" 1 "Read SW-Version" 2 "Read HW-Version" 3 "Barcode" ;
VAL_ 2332113818 M2I_Byrack_Enable_IMM27_10 1 "Deactive" 2 "Active" ;
VAL_ 2332113818 M2I_Byrack_ReVeEnable_IMM27_10 0 "invalid" 1 "Read SW-Version" 2 "Read HW-Version" 3 "Barcode" ;
VAL_ 2332113819 M2I_Byrack_Enable_IMM27_11 1 "Deactive" 2 "Active" ;
VAL_ 2332113819 M2I_Byrack_ReVeEnable_IMM27_11 0 "invalid" 1 "Read SW-Version" 2 "Read HW-Version" 3 "Barcode" ;
VAL_ 2332113820 M2I_Byrack_Enable_IMM27_12 1 "Deactive" 2 "Active" ;
VAL_ 2332113820 M2I_Byrack_ReVeEnable_IMM27_12 0 "invalid" 1 "Read SW-Version" 2 "Read HW-Version" 3 "Barcode" ;
VAL_ 2332113821 M2I_Byrack_Enable_IMM27_13 1 "Deactive" 2 "Active" ;
VAL_ 2332113821 M2I_Byrack_ReVeEnable_IMM27_13 0 "invalid" 1 "Read SW-Version" 2 "Read HW-Version" 3 "Barcode" ;
VAL_ 2332113822 M2I_Byrack_Enable_IMM27_14 1 "Deactive" 2 "Active" ;
VAL_ 2332113822 M2I_Byrack_ReVeEnable_IMM27_14 0 "invalid" 1 "Read SW-Version" 2 "Read HW-Version" 3 "Barcode" ;
VAL_ 2332113823 M2I_Byrack_Enable_IMM27_15 1 "Deactive" 2 "Active" ;
VAL_ 2332113823 M2I_Byrack_ReVeEnable_IMM27_15 0 "invalid" 1 "Read SW-Version" 2 "Read HW-Version" 3 "Barcode" ;
VAL_ 2332113824 M2I_Byrack_Enable_IMM27_16 1 "Deactive" 2 "Active" ;
VAL_ 2332113824 M2I_Byrack_ReVeEnable_IMM27_16 0 "invalid" 1 "Read SW-Version" 2 "Read HW-Version" 3 "Barcode" ;
VAL_ 2332113825 M2I_Byrack_Enable_IMM27_17 1 "Deactive" 2 "Active" ;
VAL_ 2332113825 M2I_Byrack_ReVeEnable_IMM27_17 0 "invalid" 1 "Read SW-Version" 2 "Read HW-Version" 3 "Barcode" ;
VAL_ 2332113826 M2I_Byrack_Enable_IMM27_18 1 "Deactive" 2 "Active" ;
VAL_ 2332113826 M2I_Byrack_ReVeEnable_IMM27_18 0 "invalid" 1 "Read SW-Version" 2 "Read HW-Version" 3 "Barcode" ;
VAL_ 2332113827 M2I_Byrack_Enable_IMM27_19 1 "Deactive" 2 "Active" ;
VAL_ 2332113827 M2I_Byrack_ReVeEnable_IMM27_19 0 "invalid" 1 "Read SW-Version" 2 "Read HW-Version" 3 "Barcode" ;
VAL_ 2332113828 M2I_Byrack_Enable_IMM27_20 1 "Deactive" 2 "Active" ;
VAL_ 2332113828 M2I_Byrack_ReVeEnable_IMM27_20 0 "invalid" 1 "Read SW-Version" 2 "Read HW-Version" 3 "Barcode" ;
VAL_ 2332113829 M2I_Byrack_Enable_IMM27_21 1 "Deactive" 2 "Active" ;
VAL_ 2332113829 M2I_Byrack_ReVeEnable_IMM27_21 0 "invalid" 1 "Read SW-Version" 2 "Read HW-Version" 3 "Barcode" ;
VAL_ 2332113830 M2I_Byrack_Enable_IMM27_22 1 "Deactive" 2 "Active" ;
VAL_ 2332113830 M2I_Byrack_ReVeEnable_IMM27_22 0 "invalid" 1 "Read SW-Version" 2 "Read HW-Version" 3 "Barcode" ;
VAL_ 2332113831 M2I_Byrack_Enable_IMM27_23 1 "Deactive" 2 "Active" ;
VAL_ 2332113831 M2I_Byrack_ReVeEnable_IMM27_23 0 "invalid" 1 "Read SW-Version" 2 "Read HW-Version" 3 "Barcode" ;
VAL_ 2332113832 M2I_Byrack_Enable_IMM27_24 1 "Deactive" 2 "Active" ;
VAL_ 2332113832 M2I_Byrack_ReVeEnable_IMM27_24 0 "invalid" 1 "Read SW-Version" 2 "Read HW-Version" 3 "Barcode" ;
VAL_ 2332113833 M2I_Byrack_Enable_IMM27_25 1 "Deactive" 2 "Active" ;
VAL_ 2332113833 M2I_Byrack_ReVeEnable_IMM27_25 0 "invalid" 1 "Read SW-Version" 2 "Read HW-Version" 3 "Barcode" ;
VAL_ 2332113834 M2I_Byrack_Enable_IMM27_26 1 "Deactive" 2 "Active" ;
VAL_ 2332113834 M2I_Byrack_ReVeEnable_IMM27_26 0 "invalid" 1 "Read SW-Version" 2 "Read HW-Version" 3 "Barcode" ;
VAL_ 2332113835 M2I_Byrack_Enable_IMM27_27 1 "Deactive" 2 "Active" ;
VAL_ 2332113835 M2I_Byrack_ReVeEnable_IMM27_27 0 "invalid" 1 "Read SW-Version" 2 "Read HW-Version" 3 "Barcode" ;
VAL_ 2332113836 M2I_Byrack_Enable_IMM27_28 1 "Deactive" 2 "Active" ;
VAL_ 2332113836 M2I_Byrack_ReVeEnable_IMM27_28 0 "invalid" 1 "Read SW-Version" 2 "Read HW-Version" 3 "Barcode" ;
VAL_ 2332113837 M2I_Byrack_Enable_IMM27_29 1 "Deactive" 2 "Active" ;
VAL_ 2332113837 M2I_Byrack_ReVeEnable_IMM27_29 0 "invalid" 1 "Read SW-Version" 2 "Read HW-Version" 3 "Barcode" ;
VAL_ 2332113838 M2I_Byrack_Enable_IMM27_30 1 "Deactive" 2 "Active" ;
VAL_ 2332113838 M2I_Byrack_ReVeEnable_IMM27_30 0 "invalid" 1 "Read SW-Version" 2 "Read HW-Version" 3 "Barcode" ;
VAL_ 2332113839 M2I_Byrack_Enable_IMM27_31 1 "Deactive" 2 "Active" ;
VAL_ 2332113839 M2I_Byrack_ReVeEnable_IMM27_31 0 "invalid" 1 "Read SW-Version" 2 "Read HW-Version" 3 "Barcode" ;
VAL_ 2332114065 M2I_Byrack_Enable_IMM28_01 1 "Deactive" 2 "Active" ;
VAL_ 2332114065 M2I_Byrack_ReVeEnable_IMM28_01 0 "invalid" 1 "Read SW-Version" 2 "Read HW-Version" 3 "Barcode" ;
VAL_ 2332114066 M2I_Byrack_Enable_IMM28_02 1 "Deactive" 2 "Active" ;
VAL_ 2332114066 M2I_Byrack_ReVeEnable_IMM28_02 0 "invalid" 1 "Read SW-Version" 2 "Read HW-Version" 3 "Barcode" ;
VAL_ 2332114067 M2I_Byrack_Enable_IMM28_03 1 "Deactive" 2 "Active" ;
VAL_ 2332114067 M2I_Byrack_ReVeEnable_IMM28_03 0 "invalid" 1 "Read SW-Version" 2 "Read HW-Version" 3 "Barcode" ;
VAL_ 2332114068 M2I_Byrack_Enable_IMM28_04 1 "Deactive" 2 "Active" ;
VAL_ 2332114068 M2I_Byrack_ReVeEnable_IMM28_04 0 "invalid" 1 "Read SW-Version" 2 "Read HW-Version" 3 "Barcode" ;
VAL_ 2332114069 M2I_Byrack_Enable_IMM28_05 1 "Deactive" 2 "Active" ;
VAL_ 2332114069 M2I_Byrack_ReVeEnable_IMM28_05 0 "invalid" 1 "Read SW-Version" 2 "Read HW-Version" 3 "Barcode" ;
VAL_ 2332114070 M2I_Byrack_Enable_IMM28_06 1 "Deactive" 2 "Active" ;
VAL_ 2332114070 M2I_Byrack_ReVeEnable_IMM28_06 0 "invalid" 1 "Read SW-Version" 2 "Read HW-Version" 3 "Barcode" ;
VAL_ 2332114071 M2I_Byrack_Enable_IMM28_07 1 "Deactive" 2 "Active" ;
VAL_ 2332114071 M2I_Byrack_ReVeEnable_IMM28_07 0 "invalid" 1 "Read SW-Version" 2 "Read HW-Version" 3 "Barcode" ;
VAL_ 2332114072 M2I_Byrack_Enable_IMM28_08 1 "Deactive" 2 "Active" ;
VAL_ 2332114072 M2I_Byrack_ReVeEnable_IMM28_08 0 "invalid" 1 "Read SW-Version" 2 "Read HW-Version" 3 "Barcode" ;
VAL_ 2332114073 M2I_Byrack_Enable_IMM28_09 1 "Deactive" 2 "Active" ;
VAL_ 2332114073 M2I_Byrack_ReVeEnable_IMM28_09 0 "invalid" 1 "Read SW-Version" 2 "Read HW-Version" 3 "Barcode" ;
VAL_ 2332114074 M2I_Byrack_Enable_IMM28_10 1 "Deactive" 2 "Active" ;
VAL_ 2332114074 M2I_Byrack_ReVeEnable_IMM28_10 0 "invalid" 1 "Read SW-Version" 2 "Read HW-Version" 3 "Barcode" ;
VAL_ 2332114075 M2I_Byrack_Enable_IMM28_11 1 "Deactive" 2 "Active" ;
VAL_ 2332114075 M2I_Byrack_ReVeEnable_IMM28_11 0 "invalid" 1 "Read SW-Version" 2 "Read HW-Version" 3 "Barcode" ;
VAL_ 2332114076 M2I_Byrack_Enable_IMM28_12 1 "Deactive" 2 "Active" ;
VAL_ 2332114076 M2I_Byrack_ReVeEnable_IMM28_12 0 "invalid" 1 "Read SW-Version" 2 "Read HW-Version" 3 "Barcode" ;
VAL_ 2332114077 M2I_Byrack_Enable_IMM28_13 1 "Deactive" 2 "Active" ;
VAL_ 2332114077 M2I_Byrack_ReVeEnable_IMM28_13 0 "invalid" 1 "Read SW-Version" 2 "Read HW-Version" 3 "Barcode" ;
VAL_ 2332114078 M2I_Byrack_Enable_IMM28_14 1 "Deactive" 2 "Active" ;
VAL_ 2332114078 M2I_Byrack_ReVeEnable_IMM28_14 0 "invalid" 1 "Read SW-Version" 2 "Read HW-Version" 3 "Barcode" ;
VAL_ 2332114079 M2I_Byrack_Enable_IMM28_15 1 "Deactive" 2 "Active" ;
VAL_ 2332114079 M2I_Byrack_ReVeEnable_IMM28_15 0 "invalid" 1 "Read SW-Version" 2 "Read HW-Version" 3 "Barcode" ;
VAL_ 2332114080 M2I_Byrack_Enable_IMM28_16 1 "Deactive" 2 "Active" ;
VAL_ 2332114080 M2I_Byrack_ReVeEnable_IMM28_16 0 "invalid" 1 "Read SW-Version" 2 "Read HW-Version" 3 "Barcode" ;
VAL_ 2332114081 M2I_Byrack_Enable_IMM28_17 1 "Deactive" 2 "Active" ;
VAL_ 2332114081 M2I_Byrack_ReVeEnable_IMM28_17 0 "invalid" 1 "Read SW-Version" 2 "Read HW-Version" 3 "Barcode" ;
VAL_ 2332114082 M2I_Byrack_Enable_IMM28_18 1 "Deactive" 2 "Active" ;
VAL_ 2332114082 M2I_Byrack_ReVeEnable_IMM28_18 0 "invalid" 1 "Read SW-Version" 2 "Read HW-Version" 3 "Barcode" ;
VAL_ 2332114083 M2I_Byrack_Enable_IMM28_19 1 "Deactive" 2 "Active" ;
VAL_ 2332114083 M2I_Byrack_ReVeEnable_IMM28_19 0 "invalid" 1 "Read SW-Version" 2 "Read HW-Version" 3 "Barcode" ;
VAL_ 2332114084 M2I_Byrack_Enable_IMM28_20 1 "Deactive" 2 "Active" ;
VAL_ 2332114084 M2I_Byrack_ReVeEnable_IMM28_20 0 "invalid" 1 "Read SW-Version" 2 "Read HW-Version" 3 "Barcode" ;
VAL_ 2332114085 M2I_Byrack_Enable_IMM28_21 1 "Deactive" 2 "Active" ;
VAL_ 2332114085 M2I_Byrack_ReVeEnable_IMM28_21 0 "invalid" 1 "Read SW-Version" 2 "Read HW-Version" 3 "Barcode" ;
VAL_ 2332114086 M2I_Byrack_Enable_IMM28_22 1 "Deactive" 2 "Active" ;
VAL_ 2332114086 M2I_Byrack_ReVeEnable_IMM28_22 0 "invalid" 1 "Read SW-Version" 2 "Read HW-Version" 3 "Barcode" ;
VAL_ 2332114087 M2I_Byrack_Enable_IMM28_23 1 "Deactive" 2 "Active" ;
VAL_ 2332114087 M2I_Byrack_ReVeEnable_IMM28_23 0 "invalid" 1 "Read SW-Version" 2 "Read HW-Version" 3 "Barcode" ;
VAL_ 2332114088 M2I_Byrack_Enable_IMM28_24 1 "Deactive" 2 "Active" ;
VAL_ 2332114088 M2I_Byrack_ReVeEnable_IMM28_24 0 "invalid" 1 "Read SW-Version" 2 "Read HW-Version" 3 "Barcode" ;
VAL_ 2332114089 M2I_Byrack_Enable_IMM28_25 1 "Deactive" 2 "Active" ;
VAL_ 2332114089 M2I_Byrack_ReVeEnable_IMM28_25 0 "invalid" 1 "Read SW-Version" 2 "Read HW-Version" 3 "Barcode" ;
VAL_ 2332114090 M2I_Byrack_Enable_IMM28_26 1 "Deactive" 2 "Active" ;
VAL_ 2332114090 M2I_Byrack_ReVeEnable_IMM28_26 0 "invalid" 1 "Read SW-Version" 2 "Read HW-Version" 3 "Barcode" ;
VAL_ 2332114091 M2I_Byrack_Enable_IMM28_27 1 "Deactive" 2 "Active" ;
VAL_ 2332114091 M2I_Byrack_ReVeEnable_IMM28_27 0 "invalid" 1 "Read SW-Version" 2 "Read HW-Version" 3 "Barcode" ;
VAL_ 2332114092 M2I_Byrack_Enable_IMM28_28 1 "Deactive" 2 "Active" ;
VAL_ 2332114092 M2I_Byrack_ReVeEnable_IMM28_28 0 "invalid" 1 "Read SW-Version" 2 "Read HW-Version" 3 "Barcode" ;
VAL_ 2332114093 M2I_Byrack_Enable_IMM28_29 1 "Deactive" 2 "Active" ;
VAL_ 2332114093 M2I_Byrack_ReVeEnable_IMM28_29 0 "invalid" 1 "Read SW-Version" 2 "Read HW-Version" 3 "Barcode" ;
VAL_ 2332114094 M2I_Byrack_Enable_IMM28_30 1 "Deactive" 2 "Active" ;
VAL_ 2332114094 M2I_Byrack_ReVeEnable_IMM28_30 0 "invalid" 1 "Read SW-Version" 2 "Read HW-Version" 3 "Barcode" ;
VAL_ 2332114095 M2I_Byrack_Enable_IMM28_31 1 "Deactive" 2 "Active" ;
VAL_ 2332114095 M2I_Byrack_ReVeEnable_IMM28_31 0 "invalid" 1 "Read SW-Version" 2 "Read HW-Version" 3 "Barcode" ;
VAL_ 2332114321 M2I_Byrack_Enable_IMM29_01 1 "Deactive" 2 "Active" ;
VAL_ 2332114321 M2I_Byrack_ReVeEnable_IMM29_01 0 "invalid" 1 "Read SW-Version" 2 "Read HW-Version" 3 "Barcode" ;
VAL_ 2332114322 M2I_Byrack_Enable_IMM29_02 1 "Deactive" 2 "Active" ;
VAL_ 2332114322 M2I_Byrack_ReVeEnable_IMM29_02 0 "invalid" 1 "Read SW-Version" 2 "Read HW-Version" 3 "Barcode" ;
VAL_ 2332114323 M2I_Byrack_Enable_IMM29_03 1 "Deactive" 2 "Active" ;
VAL_ 2332114323 M2I_Byrack_ReVeEnable_IMM29_03 0 "invalid" 1 "Read SW-Version" 2 "Read HW-Version" 3 "Barcode" ;
VAL_ 2332114324 M2I_Byrack_Enable_IMM29_04 1 "Deactive" 2 "Active" ;
VAL_ 2332114324 M2I_Byrack_ReVeEnable_IMM29_04 0 "invalid" 1 "Read SW-Version" 2 "Read HW-Version" 3 "Barcode" ;
VAL_ 2332114325 M2I_Byrack_Enable_IMM29_05 1 "Deactive" 2 "Active" ;
VAL_ 2332114325 M2I_Byrack_ReVeEnable_IMM29_05 0 "invalid" 1 "Read SW-Version" 2 "Read HW-Version" 3 "Barcode" ;
VAL_ 2332114326 M2I_Byrack_Enable_IMM29_06 1 "Deactive" 2 "Active" ;
VAL_ 2332114326 M2I_Byrack_ReVeEnable_IMM29_06 0 "invalid" 1 "Read SW-Version" 2 "Read HW-Version" 3 "Barcode" ;
VAL_ 2332114327 M2I_Byrack_Enable_IMM29_07 1 "Deactive" 2 "Active" ;
VAL_ 2332114327 M2I_Byrack_ReVeEnable_IMM29_07 0 "invalid" 1 "Read SW-Version" 2 "Read HW-Version" 3 "Barcode" ;
VAL_ 2332114328 M2I_Byrack_Enable_IMM29_08 1 "Deactive" 2 "Active" ;
VAL_ 2332114328 M2I_Byrack_ReVeEnable_IMM29_08 0 "invalid" 1 "Read SW-Version" 2 "Read HW-Version" 3 "Barcode" ;
VAL_ 2332114329 M2I_Byrack_Enable_IMM29_09 1 "Deactive" 2 "Active" ;
VAL_ 2332114329 M2I_Byrack_ReVeEnable_IMM29_09 0 "invalid" 1 "Read SW-Version" 2 "Read HW-Version" 3 "Barcode" ;
VAL_ 2332114330 M2I_Byrack_Enable_IMM29_10 1 "Deactive" 2 "Active" ;
VAL_ 2332114330 M2I_Byrack_ReVeEnable_IMM29_10 0 "invalid" 1 "Read SW-Version" 2 "Read HW-Version" 3 "Barcode" ;
VAL_ 2332114331 M2I_Byrack_Enable_IMM29_11 1 "Deactive" 2 "Active" ;
VAL_ 2332114331 M2I_Byrack_ReVeEnable_IMM29_11 0 "invalid" 1 "Read SW-Version" 2 "Read HW-Version" 3 "Barcode" ;
VAL_ 2332114332 M2I_Byrack_Enable_IMM29_12 1 "Deactive" 2 "Active" ;
VAL_ 2332114332 M2I_Byrack_ReVeEnable_IMM29_12 0 "invalid" 1 "Read SW-Version" 2 "Read HW-Version" 3 "Barcode" ;
VAL_ 2332114333 M2I_Byrack_Enable_IMM29_13 1 "Deactive" 2 "Active" ;
VAL_ 2332114333 M2I_Byrack_ReVeEnable_IMM29_13 0 "invalid" 1 "Read SW-Version" 2 "Read HW-Version" 3 "Barcode" ;
VAL_ 2332114334 M2I_Byrack_Enable_IMM29_14 1 "Deactive" 2 "Active" ;
VAL_ 2332114334 M2I_Byrack_ReVeEnable_IMM29_14 0 "invalid" 1 "Read SW-Version" 2 "Read HW-Version" 3 "Barcode" ;
VAL_ 2332114335 M2I_Byrack_Enable_IMM29_15 1 "Deactive" 2 "Active" ;
VAL_ 2332114335 M2I_Byrack_ReVeEnable_IMM29_15 0 "invalid" 1 "Read SW-Version" 2 "Read HW-Version" 3 "Barcode" ;
VAL_ 2332114336 M2I_Byrack_Enable_IMM29_16 1 "Deactive" 2 "Active" ;
VAL_ 2332114336 M2I_Byrack_ReVeEnable_IMM29_16 0 "invalid" 1 "Read SW-Version" 2 "Read HW-Version" 3 "Barcode" ;
VAL_ 2332114337 M2I_Byrack_Enable_IMM29_17 1 "Deactive" 2 "Active" ;
VAL_ 2332114337 M2I_Byrack_ReVeEnable_IMM29_17 0 "invalid" 1 "Read SW-Version" 2 "Read HW-Version" 3 "Barcode" ;
VAL_ 2332114338 M2I_Byrack_Enable_IMM29_18 1 "Deactive" 2 "Active" ;
VAL_ 2332114338 M2I_Byrack_ReVeEnable_IMM29_18 0 "invalid" 1 "Read SW-Version" 2 "Read HW-Version" 3 "Barcode" ;
VAL_ 2332114339 M2I_Byrack_Enable_IMM29_19 1 "Deactive" 2 "Active" ;
VAL_ 2332114339 M2I_Byrack_ReVeEnable_IMM29_19 0 "invalid" 1 "Read SW-Version" 2 "Read HW-Version" 3 "Barcode" ;
VAL_ 2332114340 M2I_Byrack_Enable_IMM29_20 1 "Deactive" 2 "Active" ;
VAL_ 2332114340 M2I_Byrack_ReVeEnable_IMM29_20 0 "invalid" 1 "Read SW-Version" 2 "Read HW-Version" 3 "Barcode" ;
VAL_ 2332114341 M2I_Byrack_Enable_IMM29_21 1 "Deactive" 2 "Active" ;
VAL_ 2332114341 M2I_Byrack_ReVeEnable_IMM29_21 0 "invalid" 1 "Read SW-Version" 2 "Read HW-Version" 3 "Barcode" ;
VAL_ 2332114342 M2I_Byrack_Enable_IMM29_22 1 "Deactive" 2 "Active" ;
VAL_ 2332114342 M2I_Byrack_ReVeEnable_IMM29_22 0 "invalid" 1 "Read SW-Version" 2 "Read HW-Version" 3 "Barcode" ;
VAL_ 2332114343 M2I_Byrack_Enable_IMM29_23 1 "Deactive" 2 "Active" ;
VAL_ 2332114343 M2I_Byrack_ReVeEnable_IMM29_23 0 "invalid" 1 "Read SW-Version" 2 "Read HW-Version" 3 "Barcode" ;
VAL_ 2332114344 M2I_Byrack_Enable_IMM29_24 1 "Deactive" 2 "Active" ;
VAL_ 2332114344 M2I_Byrack_ReVeEnable_IMM29_24 0 "invalid" 1 "Read SW-Version" 2 "Read HW-Version" 3 "Barcode" ;
VAL_ 2332114345 M2I_Byrack_Enable_IMM29_25 1 "Deactive" 2 "Active" ;
VAL_ 2332114345 M2I_Byrack_ReVeEnable_IMM29_25 0 "invalid" 1 "Read SW-Version" 2 "Read HW-Version" 3 "Barcode" ;
VAL_ 2332114346 M2I_Byrack_Enable_IMM29_26 1 "Deactive" 2 "Active" ;
VAL_ 2332114346 M2I_Byrack_ReVeEnable_IMM29_26 0 "invalid" 1 "Read SW-Version" 2 "Read HW-Version" 3 "Barcode" ;
VAL_ 2332114347 M2I_Byrack_Enable_IMM29_27 1 "Deactive" 2 "Active" ;
VAL_ 2332114347 M2I_Byrack_ReVeEnable_IMM29_27 0 "invalid" 1 "Read SW-Version" 2 "Read HW-Version" 3 "Barcode" ;
VAL_ 2332114348 M2I_Byrack_Enable_IMM29_28 1 "Deactive" 2 "Active" ;
VAL_ 2332114348 M2I_Byrack_ReVeEnable_IMM29_28 0 "invalid" 1 "Read SW-Version" 2 "Read HW-Version" 3 "Barcode" ;
VAL_ 2332114349 M2I_Byrack_Enable_IMM29_29 1 "Deactive" 2 "Active" ;
VAL_ 2332114349 M2I_Byrack_ReVeEnable_IMM29_29 0 "invalid" 1 "Read SW-Version" 2 "Read HW-Version" 3 "Barcode" ;
VAL_ 2332114350 M2I_Byrack_Enable_IMM29_30 1 "Deactive" 2 "Active" ;
VAL_ 2332114350 M2I_Byrack_ReVeEnable_IMM29_30 0 "invalid" 1 "Read SW-Version" 2 "Read HW-Version" 3 "Barcode" ;
VAL_ 2332114351 M2I_Byrack_Enable_IMM29_31 1 "Deactive" 2 "Active" ;
VAL_ 2332114351 M2I_Byrack_ReVeEnable_IMM29_31 0 "invalid" 1 "Read SW-Version" 2 "Read HW-Version" 3 "Barcode" ;
VAL_ 2332114577 M2I_Byrack_Enable_IMM30_01 1 "Deactive" 2 "Active" ;
VAL_ 2332114577 M2I_Byrack_ReVeEnable_IMM30_01 0 "invalid" 1 "Read SW-Version" 2 "Read HW-Version" 3 "Barcode" ;
VAL_ 2332114578 M2I_Byrack_Enable_IMM30_02 1 "Deactive" 2 "Active" ;
VAL_ 2332114578 M2I_Byrack_ReVeEnable_IMM30_02 0 "invalid" 1 "Read SW-Version" 2 "Read HW-Version" 3 "Barcode" ;
VAL_ 2332114579 M2I_Byrack_Enable_IMM30_03 1 "Deactive" 2 "Active" ;
VAL_ 2332114579 M2I_Byrack_ReVeEnable_IMM30_03 0 "invalid" 1 "Read SW-Version" 2 "Read HW-Version" 3 "Barcode" ;
VAL_ 2332114580 M2I_Byrack_Enable_IMM30_04 1 "Deactive" 2 "Active" ;
VAL_ 2332114580 M2I_Byrack_ReVeEnable_IMM30_04 0 "invalid" 1 "Read SW-Version" 2 "Read HW-Version" 3 "Barcode" ;
VAL_ 2332114581 M2I_Byrack_Enable_IMM30_05 1 "Deactive" 2 "Active" ;
VAL_ 2332114581 M2I_Byrack_ReVeEnable_IMM30_05 0 "invalid" 1 "Read SW-Version" 2 "Read HW-Version" 3 "Barcode" ;
VAL_ 2332114582 M2I_Byrack_Enable_IMM30_06 1 "Deactive" 2 "Active" ;
VAL_ 2332114582 M2I_Byrack_ReVeEnable_IMM30_06 0 "invalid" 1 "Read SW-Version" 2 "Read HW-Version" 3 "Barcode" ;
VAL_ 2332114583 M2I_Byrack_Enable_IMM30_07 1 "Deactive" 2 "Active" ;
VAL_ 2332114583 M2I_Byrack_ReVeEnable_IMM30_07 0 "invalid" 1 "Read SW-Version" 2 "Read HW-Version" 3 "Barcode" ;
VAL_ 2332114584 M2I_Byrack_Enable_IMM30_08 1 "Deactive" 2 "Active" ;
VAL_ 2332114584 M2I_Byrack_ReVeEnable_IMM30_08 0 "invalid" 1 "Read SW-Version" 2 "Read HW-Version" 3 "Barcode" ;
VAL_ 2332114585 M2I_Byrack_Enable_IMM30_09 1 "Deactive" 2 "Active" ;
VAL_ 2332114585 M2I_Byrack_ReVeEnable_IMM30_09 0 "invalid" 1 "Read SW-Version" 2 "Read HW-Version" 3 "Barcode" ;
VAL_ 2332114586 M2I_Byrack_Enable_IMM30_10 1 "Deactive" 2 "Active" ;
VAL_ 2332114586 M2I_Byrack_ReVeEnable_IMM30_10 0 "invalid" 1 "Read SW-Version" 2 "Read HW-Version" 3 "Barcode" ;
VAL_ 2332114587 M2I_Byrack_Enable_IMM30_11 1 "Deactive" 2 "Active" ;
VAL_ 2332114587 M2I_Byrack_ReVeEnable_IMM30_11 0 "invalid" 1 "Read SW-Version" 2 "Read HW-Version" 3 "Barcode" ;
VAL_ 2332114588 M2I_Byrack_Enable_IMM30_12 1 "Deactive" 2 "Active" ;
VAL_ 2332114588 M2I_Byrack_ReVeEnable_IMM30_12 0 "invalid" 1 "Read SW-Version" 2 "Read HW-Version" 3 "Barcode" ;
VAL_ 2332114589 M2I_Byrack_Enable_IMM30_13 1 "Deactive" 2 "Active" ;
VAL_ 2332114589 M2I_Byrack_ReVeEnable_IMM30_13 0 "invalid" 1 "Read SW-Version" 2 "Read HW-Version" 3 "Barcode" ;
VAL_ 2332114590 M2I_Byrack_Enable_IMM30_14 1 "Deactive" 2 "Active" ;
VAL_ 2332114590 M2I_Byrack_ReVeEnable_IMM30_14 0 "invalid" 1 "Read SW-Version" 2 "Read HW-Version" 3 "Barcode" ;
VAL_ 2332114591 M2I_Byrack_Enable_IMM30_15 1 "Deactive" 2 "Active" ;
VAL_ 2332114591 M2I_Byrack_ReVeEnable_IMM30_15 0 "invalid" 1 "Read SW-Version" 2 "Read HW-Version" 3 "Barcode" ;
VAL_ 2332114592 M2I_Byrack_Enable_IMM30_16 1 "Deactive" 2 "Active" ;
VAL_ 2332114592 M2I_Byrack_ReVeEnable_IMM30_16 0 "invalid" 1 "Read SW-Version" 2 "Read HW-Version" 3 "Barcode" ;
VAL_ 2332114593 M2I_Byrack_Enable_IMM30_17 1 "Deactive" 2 "Active" ;
VAL_ 2332114593 M2I_Byrack_ReVeEnable_IMM30_17 0 "invalid" 1 "Read SW-Version" 2 "Read HW-Version" 3 "Barcode" ;
VAL_ 2332114594 M2I_Byrack_Enable_IMM30_18 1 "Deactive" 2 "Active" ;
VAL_ 2332114594 M2I_Byrack_ReVeEnable_IMM30_18 0 "invalid" 1 "Read SW-Version" 2 "Read HW-Version" 3 "Barcode" ;
VAL_ 2332114595 M2I_Byrack_Enable_IMM30_19 1 "Deactive" 2 "Active" ;
VAL_ 2332114595 M2I_Byrack_ReVeEnable_IMM30_19 0 "invalid" 1 "Read SW-Version" 2 "Read HW-Version" 3 "Barcode" ;
VAL_ 2332114596 M2I_Byrack_Enable_IMM30_20 1 "Deactive" 2 "Active" ;
VAL_ 2332114596 M2I_Byrack_ReVeEnable_IMM30_20 0 "invalid" 1 "Read SW-Version" 2 "Read HW-Version" 3 "Barcode" ;
VAL_ 2332114597 M2I_Byrack_Enable_IMM30_21 1 "Deactive" 2 "Active" ;
VAL_ 2332114597 M2I_Byrack_ReVeEnable_IMM30_21 0 "invalid" 1 "Read SW-Version" 2 "Read HW-Version" 3 "Barcode" ;
VAL_ 2332114598 M2I_Byrack_Enable_IMM30_22 1 "Deactive" 2 "Active" ;
VAL_ 2332114598 M2I_Byrack_ReVeEnable_IMM30_22 0 "invalid" 1 "Read SW-Version" 2 "Read HW-Version" 3 "Barcode" ;
VAL_ 2332114599 M2I_Byrack_Enable_IMM30_23 1 "Deactive" 2 "Active" ;
VAL_ 2332114599 M2I_Byrack_ReVeEnable_IMM30_23 0 "invalid" 1 "Read SW-Version" 2 "Read HW-Version" 3 "Barcode" ;
VAL_ 2332114600 M2I_Byrack_Enable_IMM30_24 1 "Deactive" 2 "Active" ;
VAL_ 2332114600 M2I_Byrack_ReVeEnable_IMM30_24 0 "invalid" 1 "Read SW-Version" 2 "Read HW-Version" 3 "Barcode" ;
VAL_ 2332114601 M2I_Byrack_Enable_IMM30_25 1 "Deactive" 2 "Active" ;
VAL_ 2332114601 M2I_Byrack_ReVeEnable_IMM30_25 0 "invalid" 1 "Read SW-Version" 2 "Read HW-Version" 3 "Barcode" ;
VAL_ 2332114602 M2I_Byrack_Enable_IMM30_26 1 "Deactive" 2 "Active" ;
VAL_ 2332114602 M2I_Byrack_ReVeEnable_IMM30_26 0 "invalid" 1 "Read SW-Version" 2 "Read HW-Version" 3 "Barcode" ;
VAL_ 2332114603 M2I_Byrack_Enable_IMM30_27 1 "Deactive" 2 "Active" ;
VAL_ 2332114603 M2I_Byrack_ReVeEnable_IMM30_27 0 "invalid" 1 "Read SW-Version" 2 "Read HW-Version" 3 "Barcode" ;
VAL_ 2332114604 M2I_Byrack_Enable_IMM30_28 1 "Deactive" 2 "Active" ;
VAL_ 2332114604 M2I_Byrack_ReVeEnable_IMM30_28 0 "invalid" 1 "Read SW-Version" 2 "Read HW-Version" 3 "Barcode" ;
VAL_ 2332114605 M2I_Byrack_Enable_IMM30_29 1 "Deactive" 2 "Active" ;
VAL_ 2332114605 M2I_Byrack_ReVeEnable_IMM30_29 0 "invalid" 1 "Read SW-Version" 2 "Read HW-Version" 3 "Barcode" ;
VAL_ 2332114606 M2I_Byrack_Enable_IMM30_30 1 "Deactive" 2 "Active" ;
VAL_ 2332114606 M2I_Byrack_ReVeEnable_IMM30_30 0 "invalid" 1 "Read SW-Version" 2 "Read HW-Version" 3 "Barcode" ;
VAL_ 2332114607 M2I_Byrack_Enable_IMM30_31 1 "Deactive" 2 "Active" ;
VAL_ 2332114607 M2I_Byrack_ReVeEnable_IMM30_31 0 "invalid" 1 "Read SW-Version" 2 "Read HW-Version" 3 "Barcode" ;
VAL_ 2332114833 M2I_Byrack_Enable_IMM31_01 1 "Deactive" 2 "Active" ;
VAL_ 2332114833 M2I_Byrack_ReVeEnable_IMM31_01 0 "invalid" 1 "Read SW-Version" 2 "Read HW-Version" 3 "Barcode" ;
VAL_ 2332114834 M2I_Byrack_Enable_IMM31_02 1 "Deactive" 2 "Active" ;
VAL_ 2332114834 M2I_Byrack_ReVeEnable_IMM31_02 0 "invalid" 1 "Read SW-Version" 2 "Read HW-Version" 3 "Barcode" ;
VAL_ 2332114835 M2I_Byrack_Enable_IMM31_03 1 "Deactive" 2 "Active" ;
VAL_ 2332114835 M2I_Byrack_ReVeEnable_IMM31_03 0 "invalid" 1 "Read SW-Version" 2 "Read HW-Version" 3 "Barcode" ;
VAL_ 2332114836 M2I_Byrack_Enable_IMM31_04 1 "Deactive" 2 "Active" ;
VAL_ 2332114836 M2I_Byrack_ReVeEnable_IMM31_04 0 "invalid" 1 "Read SW-Version" 2 "Read HW-Version" 3 "Barcode" ;
VAL_ 2332114837 M2I_Byrack_Enable_IMM31_05 1 "Deactive" 2 "Active" ;
VAL_ 2332114837 M2I_Byrack_ReVeEnable_IMM31_05 0 "invalid" 1 "Read SW-Version" 2 "Read HW-Version" 3 "Barcode" ;
VAL_ 2332114838 M2I_Byrack_Enable_IMM31_06 1 "Deactive" 2 "Active" ;
VAL_ 2332114838 M2I_Byrack_ReVeEnable_IMM31_06 0 "invalid" 1 "Read SW-Version" 2 "Read HW-Version" 3 "Barcode" ;
VAL_ 2332114839 M2I_Byrack_Enable_IMM31_07 1 "Deactive" 2 "Active" ;
VAL_ 2332114839 M2I_Byrack_ReVeEnable_IMM31_07 0 "invalid" 1 "Read SW-Version" 2 "Read HW-Version" 3 "Barcode" ;
VAL_ 2332114840 M2I_Byrack_Enable_IMM31_08 1 "Deactive" 2 "Active" ;
VAL_ 2332114840 M2I_Byrack_ReVeEnable_IMM31_08 0 "invalid" 1 "Read SW-Version" 2 "Read HW-Version" 3 "Barcode" ;
VAL_ 2332114841 M2I_Byrack_Enable_IMM31_09 1 "Deactive" 2 "Active" ;
VAL_ 2332114841 M2I_Byrack_ReVeEnable_IMM31_09 0 "invalid" 1 "Read SW-Version" 2 "Read HW-Version" 3 "Barcode" ;
VAL_ 2332114842 M2I_Byrack_Enable_IMM31_10 1 "Deactive" 2 "Active" ;
VAL_ 2332114842 M2I_Byrack_ReVeEnable_IMM31_10 0 "invalid" 1 "Read SW-Version" 2 "Read HW-Version" 3 "Barcode" ;
VAL_ 2332114843 M2I_Byrack_Enable_IMM31_11 1 "Deactive" 2 "Active" ;
VAL_ 2332114843 M2I_Byrack_ReVeEnable_IMM31_11 0 "invalid" 1 "Read SW-Version" 2 "Read HW-Version" 3 "Barcode" ;
VAL_ 2332114844 M2I_Byrack_Enable_IMM31_12 1 "Deactive" 2 "Active" ;
VAL_ 2332114844 M2I_Byrack_ReVeEnable_IMM31_12 0 "invalid" 1 "Read SW-Version" 2 "Read HW-Version" 3 "Barcode" ;
VAL_ 2332114845 M2I_Byrack_Enable_IMM31_13 1 "Deactive" 2 "Active" ;
VAL_ 2332114845 M2I_Byrack_ReVeEnable_IMM31_13 0 "invalid" 1 "Read SW-Version" 2 "Read HW-Version" 3 "Barcode" ;
VAL_ 2332114846 M2I_Byrack_Enable_IMM31_14 1 "Deactive" 2 "Active" ;
VAL_ 2332114846 M2I_Byrack_ReVeEnable_IMM31_14 0 "invalid" 1 "Read SW-Version" 2 "Read HW-Version" 3 "Barcode" ;
VAL_ 2332114847 M2I_Byrack_Enable_IMM31_15 1 "Deactive" 2 "Active" ;
VAL_ 2332114847 M2I_Byrack_ReVeEnable_IMM31_15 0 "invalid" 1 "Read SW-Version" 2 "Read HW-Version" 3 "Barcode" ;
VAL_ 2332114848 M2I_Byrack_Enable_IMM31_16 1 "Deactive" 2 "Active" ;
VAL_ 2332114848 M2I_Byrack_ReVeEnable_IMM31_16 0 "invalid" 1 "Read SW-Version" 2 "Read HW-Version" 3 "Barcode" ;
VAL_ 2332114849 M2I_Byrack_Enable_IMM31_17 1 "Deactive" 2 "Active" ;
VAL_ 2332114849 M2I_Byrack_ReVeEnable_IMM31_17 0 "invalid" 1 "Read SW-Version" 2 "Read HW-Version" 3 "Barcode" ;
VAL_ 2332114850 M2I_Byrack_Enable_IMM31_18 1 "Deactive" 2 "Active" ;
VAL_ 2332114850 M2I_Byrack_ReVeEnable_IMM31_18 0 "invalid" 1 "Read SW-Version" 2 "Read HW-Version" 3 "Barcode" ;
VAL_ 2332114851 M2I_Byrack_Enable_IMM31_19 1 "Deactive" 2 "Active" ;
VAL_ 2332114851 M2I_Byrack_ReVeEnable_IMM31_19 0 "invalid" 1 "Read SW-Version" 2 "Read HW-Version" 3 "Barcode" ;
VAL_ 2332114852 M2I_Byrack_Enable_IMM31_20 1 "Deactive" 2 "Active" ;
VAL_ 2332114852 M2I_Byrack_ReVeEnable_IMM31_20 0 "invalid" 1 "Read SW-Version" 2 "Read HW-Version" 3 "Barcode" ;
VAL_ 2332114853 M2I_Byrack_Enable_IMM31_21 1 "Deactive" 2 "Active" ;
VAL_ 2332114853 M2I_Byrack_ReVeEnable_IMM31_21 0 "invalid" 1 "Read SW-Version" 2 "Read HW-Version" 3 "Barcode" ;
VAL_ 2332114854 M2I_Byrack_Enable_IMM31_22 1 "Deactive" 2 "Active" ;
VAL_ 2332114854 M2I_Byrack_ReVeEnable_IMM31_22 0 "invalid" 1 "Read SW-Version" 2 "Read HW-Version" 3 "Barcode" ;
VAL_ 2332114855 M2I_Byrack_Enable_IMM31_23 1 "Deactive" 2 "Active" ;
VAL_ 2332114855 M2I_Byrack_ReVeEnable_IMM31_23 0 "invalid" 1 "Read SW-Version" 2 "Read HW-Version" 3 "Barcode" ;
VAL_ 2332114856 M2I_Byrack_Enable_IMM31_24 1 "Deactive" 2 "Active" ;
VAL_ 2332114856 M2I_Byrack_ReVeEnable_IMM31_24 0 "invalid" 1 "Read SW-Version" 2 "Read HW-Version" 3 "Barcode" ;
VAL_ 2332114857 M2I_Byrack_Enable_IMM31_25 1 "Deactive" 2 "Active" ;
VAL_ 2332114857 M2I_Byrack_ReVeEnable_IMM31_25 0 "invalid" 1 "Read SW-Version" 2 "Read HW-Version" 3 "Barcode" ;
VAL_ 2332114858 M2I_Byrack_Enable_IMM31_26 1 "Deactive" 2 "Active" ;
VAL_ 2332114858 M2I_Byrack_ReVeEnable_IMM31_26 0 "invalid" 1 "Read SW-Version" 2 "Read HW-Version" 3 "Barcode" ;
VAL_ 2332114859 M2I_Byrack_Enable_IMM31_27 1 "Deactive" 2 "Active" ;
VAL_ 2332114859 M2I_Byrack_ReVeEnable_IMM31_27 0 "invalid" 1 "Read SW-Version" 2 "Read HW-Version" 3 "Barcode" ;
VAL_ 2332114860 M2I_Byrack_Enable_IMM31_28 1 "Deactive" 2 "Active" ;
VAL_ 2332114860 M2I_Byrack_ReVeEnable_IMM31_28 0 "invalid" 1 "Read SW-Version" 2 "Read HW-Version" 3 "Barcode" ;
VAL_ 2332114861 M2I_Byrack_Enable_IMM31_29 1 "Deactive" 2 "Active" ;
VAL_ 2332114861 M2I_Byrack_ReVeEnable_IMM31_29 0 "invalid" 1 "Read SW-Version" 2 "Read HW-Version" 3 "Barcode" ;
VAL_ 2332114862 M2I_Byrack_Enable_IMM31_30 1 "Deactive" 2 "Active" ;
VAL_ 2332114862 M2I_Byrack_ReVeEnable_IMM31_30 0 "invalid" 1 "Read SW-Version" 2 "Read HW-Version" 3 "Barcode" ;
VAL_ 2332114863 M2I_Byrack_Enable_IMM31_31 1 "Deactive" 2 "Active" ;
VAL_ 2332114863 M2I_Byrack_ReVeEnable_IMM31_31 0 "invalid" 1 "Read SW-Version" 2 "Read HW-Version" 3 "Barcode" ;
VAL_ 2333077137 Reserved_01 0 "正常" 1 "故障" ;
VAL_ 2333077138 Reserved_02 0 "正常" 1 "故障" ;
VAL_ 2333077139 Reserved_03 0 "正常" 1 "故障" ;
VAL_ 2333077140 Reserved_04 0 "正常" 1 "故障" ;
VAL_ 2333077141 Reserved_05 0 "正常" 1 "故障" ;
VAL_ 2333077142 Reserved_06 0 "正常" 1 "故障" ;
VAL_ 2333077143 Reserved_07 0 "正常" 1 "故障" ;
VAL_ 2333077144 Reserved_08 0 "正常" 1 "故障" ;
VAL_ 2333077145 Reserved_09 0 "正常" 1 "故障" ;
VAL_ 2333077146 Reserved_10 0 "正常" 1 "故障" ;
VAL_ 2333077147 Reserved_11 0 "正常" 1 "故障" ;
VERSION ""

NS_ :

BS_:

BU_: MBMU PC SBMU IMM ETH DCDC LEMS

BO_ 2333077148 M2P_SUMDATA14__12: 8 MBMU
 SG_ Reserved_12 : 0|64@1+ (1,0) [0|1.84467440737096E+019] ""  PC

BO_ 2333077149 M2P_SUMDATA14__13: 8 MBMU
 SG_ Reserved_13 : 0|64@1+ (1,0) [0|1.84467440737096E+019] ""  PC

BO_ 2333077150 M2P_SUMDATA14__14: 8 MBMU
 SG_ Reserved_14 : 0|64@1+ (1,0) [0|1.84467440737096E+019] ""  PC

BO_ 2333077151 M2P_SUMDATA14__15: 8 MBMU
 SG_ Reserved_15 : 0|64@1+ (1,0) [0|1.84467440737096E+019] ""  PC

BO_ 2333077152 M2P_SUMDATA14__16: 8 MBMU
 SG_ Reserved_16 : 0|64@1+ (1,0) [0|1.84467440737096E+019] ""  PC

BO_ 2333077153 M2P_SUMDATA14__17: 8 MBMU
 SG_ Reserved_17 : 0|64@1+ (1,0) [0|1.84467440737096E+019] ""  PC

BO_ 2333077154 M2P_SUMDATA14__18: 8 MBMU
 SG_ Reserved_18 : 0|64@1+ (1,0) [0|1.84467440737096E+019] ""  PC

BO_ 2333077155 M2P_SUMDATA14__19: 8 MBMU
 SG_ Reserved_19 : 0|64@1+ (1,0) [0|1.84467440737096E+019] ""  PC

BO_ 2333077156 M2P_SUMDATA14__20: 8 MBMU
 SG_ Reserved_20 : 0|64@1+ (1,0) [0|1.84467440737096E+019] ""  PC

BO_ 2333077157 M2P_SUMDATA14__21: 8 MBMU
 SG_ Reserved_21 : 0|64@1+ (1,0) [0|1.84467440737096E+019] ""  PC

BO_ 2333077158 M2P_SUMDATA14__22: 8 MBMU
 SG_ Reserved_22 : 0|64@1+ (1,0) [0|1.84467440737096E+019] ""  PC

BO_ 2333077159 M2P_SUMDATA14__23: 8 MBMU
 SG_ Reserved_23 : 0|64@1+ (1,0) [0|1.84467440737096E+019] ""  PC

BO_ 2333077160 M2P_SUMDATA14__24: 8 MBMU
 SG_ Reserved_24 : 0|64@1+ (1,0) [0|1.84467440737096E+019] ""  PC

BO_ 2333077161 M2P_SUMDATA14__25: 8 MBMU
 SG_ Reserved_25 : 0|64@1+ (1,0) [0|1.84467440737096E+019] ""  PC

BO_ 2333077162 M2P_SUMDATA14__26: 8 MBMU
 SG_ Reserved_26 : 0|64@1+ (1,0) [0|1.84467440737096E+019] ""  PC

BO_ 2333077163 M2P_SUMDATA14__27: 8 MBMU
 SG_ Reserved_27 : 0|64@1+ (1,0) [0|1.84467440737096E+019] ""  PC

BO_ 2333077164 M2P_SUMDATA14__28: 8 MBMU
 SG_ Reserved_28 : 0|64@1+ (1,0) [0|1.84467440737096E+019] ""  PC

BO_ 2333077165 M2P_SUMDATA14__29: 8 MBMU
 SG_ Reserved_29 : 0|64@1+ (1,0) [0|1.84467440737096E+019] ""  PC

BO_ 2333077166 M2P_SUMDATA14__30: 8 MBMU
 SG_ Reserved_30 : 0|64@1+ (1,0) [0|1.84467440737096E+019] ""  PC

BO_ 2333077167 M2P_SUMDATA14__31: 8 MBMU
 SG_ Reserved_31 : 0|64@1+ (1,0) [0|1.84467440737096E+019] ""  PC

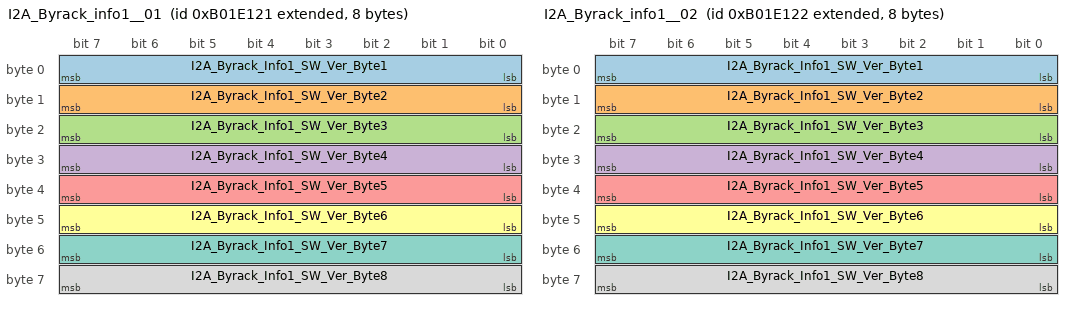
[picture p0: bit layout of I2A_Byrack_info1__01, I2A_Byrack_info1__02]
BO_ 2332156193 I2A_Byrack_info1__01: 8 IMM
 SG_ I2A_Byrack_Info1_SW_Ver_Byte1 : 0|8@1+ (1,0) [0|255] ""  MBMU
 SG_ I2A_Byrack_Info1_SW_Ver_Byte2 : 8|8@1+ (1,0) [0|255] ""  MBMU
 SG_ I2A_Byrack_Info1_SW_Ver_Byte3 : 16|8@1+ (1,0) [0|255] ""  MBMU
 SG_ I2A_Byrack_Info1_SW_Ver_Byte4 : 24|8@1+ (1,0) [0|255] ""  MBMU
 SG_ I2A_Byrack_Info1_SW_Ver_Byte5 : 32|8@1+ (1,0) [0|255] ""  MBMU
 SG_ I2A_Byrack_Info1_SW_Ver_Byte6 : 40|8@1+ (1,0) [0|255] ""  MBMU
 SG_ I2A_Byrack_Info1_SW_Ver_Byte7 : 48|8@1+ (1,0) [0|255] ""  MBMU
 SG_ I2A_Byrack_Info1_SW_Ver_Byte8 : 56|8@1+ (1,0) [0|255] ""  MBMU

BO_ 2332156194 I2A_Byrack_info1__02: 8 IMM
 SG_ I2A_Byrack_Info1_SW_Ver_Byte1 : 0|8@1+ (1,0) [0|255] ""  MBMU
 SG_ I2A_Byrack_Info1_SW_Ver_Byte2 : 8|8@1+ (1,0) [0|255] ""  MBMU
 SG_ I2A_Byrack_Info1_SW_Ver_Byte3 : 16|8@1+ (1,0) [0|255] ""  MBMU
 SG_ I2A_Byrack_Info1_SW_Ver_Byte4 : 24|8@1+ (1,0) [0|255] ""  MBMU
 SG_ I2A_Byrack_Info1_SW_Ver_Byte5 : 32|8@1+ (1,0) [0|255] ""  MBMU
 SG_ I2A_Byrack_Info1_SW_Ver_Byte6 : 40|8@1+ (1,0) [0|255] ""  MBMU
 SG_ I2A_Byrack_Info1_SW_Ver_Byte7 : 48|8@1+ (1,0) [0|255] ""  MBMU
 SG_ I2A_Byrack_Info1_SW_Ver_Byte8 : 56|8@1+ (1,0) [0|255] ""  MBMU

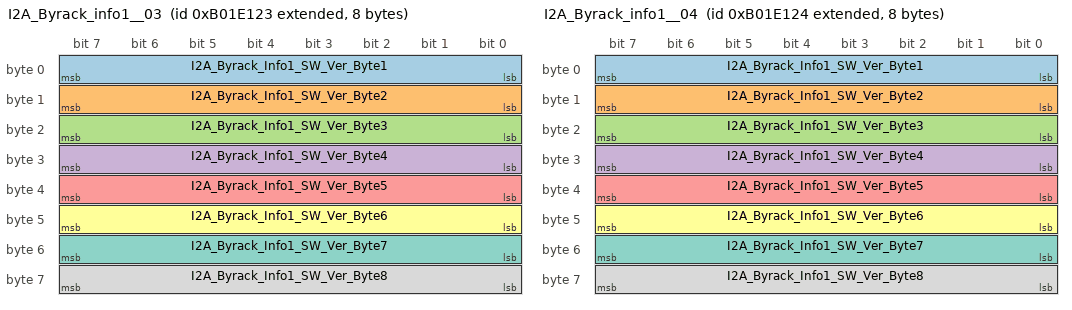
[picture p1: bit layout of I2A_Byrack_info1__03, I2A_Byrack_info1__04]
BO_ 2332156195 I2A_Byrack_info1__03: 8 IMM
 SG_ I2A_Byrack_Info1_SW_Ver_Byte1 : 0|8@1+ (1,0) [0|255] ""  MBMU
 SG_ I2A_Byrack_Info1_SW_Ver_Byte2 : 8|8@1+ (1,0) [0|255] ""  MBMU
 SG_ I2A_Byrack_Info1_SW_Ver_Byte3 : 16|8@1+ (1,0) [0|255] ""  MBMU
 SG_ I2A_Byrack_Info1_SW_Ver_Byte4 : 24|8@1+ (1,0) [0|255] ""  MBMU
 SG_ I2A_Byrack_Info1_SW_Ver_Byte5 : 32|8@1+ (1,0) [0|255] ""  MBMU
 SG_ I2A_Byrack_Info1_SW_Ver_Byte6 : 40|8@1+ (1,0) [0|255] ""  MBMU
 SG_ I2A_Byrack_Info1_SW_Ver_Byte7 : 48|8@1+ (1,0) [0|255] ""  MBMU
 SG_ I2A_Byrack_Info1_SW_Ver_Byte8 : 56|8@1+ (1,0) [0|255] ""  MBMU

BO_ 2332156196 I2A_Byrack_info1__04: 8 IMM
 SG_ I2A_Byrack_Info1_SW_Ver_Byte1 : 0|8@1+ (1,0) [0|255] ""  MBMU
 SG_ I2A_Byrack_Info1_SW_Ver_Byte2 : 8|8@1+ (1,0) [0|255] ""  MBMU
 SG_ I2A_Byrack_Info1_SW_Ver_Byte3 : 16|8@1+ (1,0) [0|255] ""  MBMU
 SG_ I2A_Byrack_Info1_SW_Ver_Byte4 : 24|8@1+ (1,0) [0|255] ""  MBMU
 SG_ I2A_Byrack_Info1_SW_Ver_Byte5 : 32|8@1+ (1,0) [0|255] ""  MBMU
 SG_ I2A_Byrack_Info1_SW_Ver_Byte6 : 40|8@1+ (1,0) [0|255] ""  MBMU
 SG_ I2A_Byrack_Info1_SW_Ver_Byte7 : 48|8@1+ (1,0) [0|255] ""  MBMU
 SG_ I2A_Byrack_Info1_SW_Ver_Byte8 : 56|8@1+ (1,0) [0|255] ""  MBMU

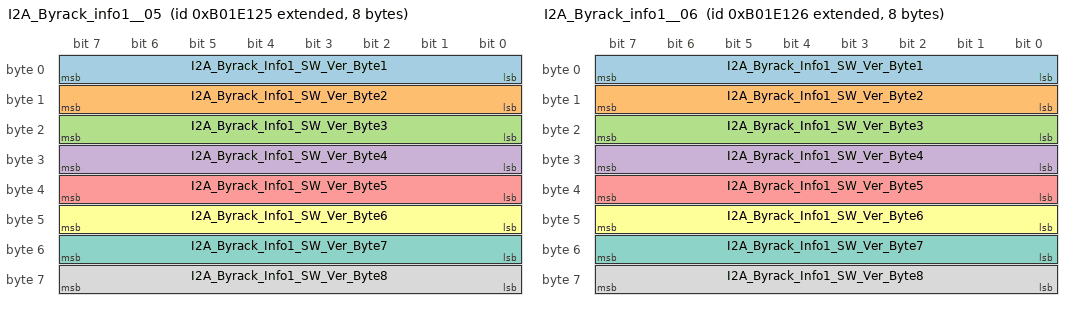
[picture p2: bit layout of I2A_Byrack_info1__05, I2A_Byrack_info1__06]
BO_ 2332156197 I2A_Byrack_info1__05: 8 IMM
 SG_ I2A_Byrack_Info1_SW_Ver_Byte1 : 0|8@1+ (1,0) [0|255] ""  MBMU
 SG_ I2A_Byrack_Info1_SW_Ver_Byte2 : 8|8@1+ (1,0) [0|255] ""  MBMU
 SG_ I2A_Byrack_Info1_SW_Ver_Byte3 : 16|8@1+ (1,0) [0|255] ""  MBMU
 SG_ I2A_Byrack_Info1_SW_Ver_Byte4 : 24|8@1+ (1,0) [0|255] ""  MBMU
 SG_ I2A_Byrack_Info1_SW_Ver_Byte5 : 32|8@1+ (1,0) [0|255] ""  MBMU
 SG_ I2A_Byrack_Info1_SW_Ver_Byte6 : 40|8@1+ (1,0) [0|255] ""  MBMU
 SG_ I2A_Byrack_Info1_SW_Ver_Byte7 : 48|8@1+ (1,0) [0|255] ""  MBMU
 SG_ I2A_Byrack_Info1_SW_Ver_Byte8 : 56|8@1+ (1,0) [0|255] ""  MBMU

BO_ 2332156198 I2A_Byrack_info1__06: 8 IMM
 SG_ I2A_Byrack_Info1_SW_Ver_Byte1 : 0|8@1+ (1,0) [0|255] ""  MBMU
 SG_ I2A_Byrack_Info1_SW_Ver_Byte2 : 8|8@1+ (1,0) [0|255] ""  MBMU
 SG_ I2A_Byrack_Info1_SW_Ver_Byte3 : 16|8@1+ (1,0) [0|255] ""  MBMU
 SG_ I2A_Byrack_Info1_SW_Ver_Byte4 : 24|8@1+ (1,0) [0|255] ""  MBMU
 SG_ I2A_Byrack_Info1_SW_Ver_Byte5 : 32|8@1+ (1,0) [0|255] ""  MBMU
 SG_ I2A_Byrack_Info1_SW_Ver_Byte6 : 40|8@1+ (1,0) [0|255] ""  MBMU
 SG_ I2A_Byrack_Info1_SW_Ver_Byte7 : 48|8@1+ (1,0) [0|255] ""  MBMU
 SG_ I2A_Byrack_Info1_SW_Ver_Byte8 : 56|8@1+ (1,0) [0|255] ""  MBMU

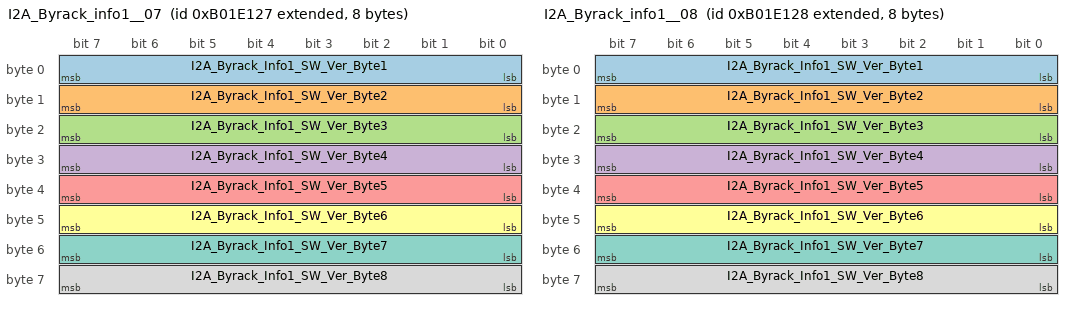
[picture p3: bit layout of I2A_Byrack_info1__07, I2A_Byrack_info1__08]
BO_ 2332156199 I2A_Byrack_info1__07: 8 IMM
 SG_ I2A_Byrack_Info1_SW_Ver_Byte1 : 0|8@1+ (1,0) [0|255] ""  MBMU
 SG_ I2A_Byrack_Info1_SW_Ver_Byte2 : 8|8@1+ (1,0) [0|255] ""  MBMU
 SG_ I2A_Byrack_Info1_SW_Ver_Byte3 : 16|8@1+ (1,0) [0|255] ""  MBMU
 SG_ I2A_Byrack_Info1_SW_Ver_Byte4 : 24|8@1+ (1,0) [0|255] ""  MBMU
 SG_ I2A_Byrack_Info1_SW_Ver_Byte5 : 32|8@1+ (1,0) [0|255] ""  MBMU
 SG_ I2A_Byrack_Info1_SW_Ver_Byte6 : 40|8@1+ (1,0) [0|255] ""  MBMU
 SG_ I2A_Byrack_Info1_SW_Ver_Byte7 : 48|8@1+ (1,0) [0|255] ""  MBMU
 SG_ I2A_Byrack_Info1_SW_Ver_Byte8 : 56|8@1+ (1,0) [0|255] ""  MBMU

BO_ 2332156200 I2A_Byrack_info1__08: 8 IMM
 SG_ I2A_Byrack_Info1_SW_Ver_Byte1 : 0|8@1+ (1,0) [0|255] ""  MBMU
 SG_ I2A_Byrack_Info1_SW_Ver_Byte2 : 8|8@1+ (1,0) [0|255] ""  MBMU
 SG_ I2A_Byrack_Info1_SW_Ver_Byte3 : 16|8@1+ (1,0) [0|255] ""  MBMU
 SG_ I2A_Byrack_Info1_SW_Ver_Byte4 : 24|8@1+ (1,0) [0|255] ""  MBMU
 SG_ I2A_Byrack_Info1_SW_Ver_Byte5 : 32|8@1+ (1,0) [0|255] ""  MBMU
 SG_ I2A_Byrack_Info1_SW_Ver_Byte6 : 40|8@1+ (1,0) [0|255] ""  MBMU
 SG_ I2A_Byrack_Info1_SW_Ver_Byte7 : 48|8@1+ (1,0) [0|255] ""  MBMU
 SG_ I2A_Byrack_Info1_SW_Ver_Byte8 : 56|8@1+ (1,0) [0|255] ""  MBMU

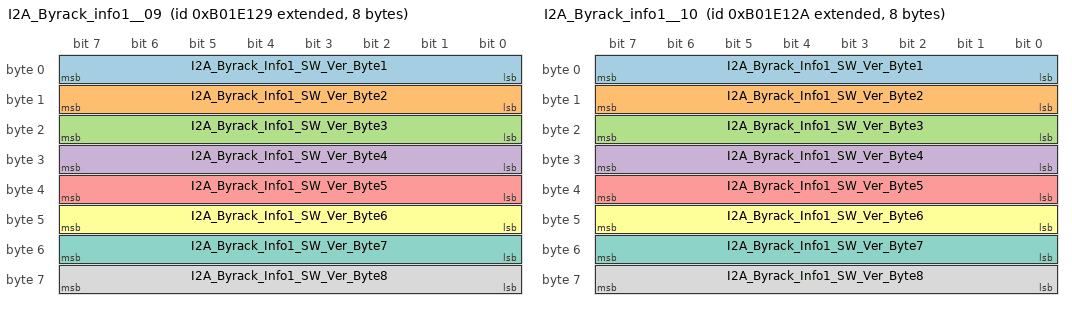
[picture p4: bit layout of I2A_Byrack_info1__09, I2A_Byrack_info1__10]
BO_ 2332156201 I2A_Byrack_info1__09: 8 IMM
 SG_ I2A_Byrack_Info1_SW_Ver_Byte1 : 0|8@1+ (1,0) [0|255] ""  MBMU
 SG_ I2A_Byrack_Info1_SW_Ver_Byte2 : 8|8@1+ (1,0) [0|255] ""  MBMU
 SG_ I2A_Byrack_Info1_SW_Ver_Byte3 : 16|8@1+ (1,0) [0|255] ""  MBMU
 SG_ I2A_Byrack_Info1_SW_Ver_Byte4 : 24|8@1+ (1,0) [0|255] ""  MBMU
 SG_ I2A_Byrack_Info1_SW_Ver_Byte5 : 32|8@1+ (1,0) [0|255] ""  MBMU
 SG_ I2A_Byrack_Info1_SW_Ver_Byte6 : 40|8@1+ (1,0) [0|255] ""  MBMU
 SG_ I2A_Byrack_Info1_SW_Ver_Byte7 : 48|8@1+ (1,0) [0|255] ""  MBMU
 SG_ I2A_Byrack_Info1_SW_Ver_Byte8 : 56|8@1+ (1,0) [0|255] ""  MBMU

BO_ 2332156202 I2A_Byrack_info1__10: 8 IMM
 SG_ I2A_Byrack_Info1_SW_Ver_Byte1 : 0|8@1+ (1,0) [0|255] ""  MBMU
 SG_ I2A_Byrack_Info1_SW_Ver_Byte2 : 8|8@1+ (1,0) [0|255] ""  MBMU
 SG_ I2A_Byrack_Info1_SW_Ver_Byte3 : 16|8@1+ (1,0) [0|255] ""  MBMU
 SG_ I2A_Byrack_Info1_SW_Ver_Byte4 : 24|8@1+ (1,0) [0|255] ""  MBMU
 SG_ I2A_Byrack_Info1_SW_Ver_Byte5 : 32|8@1+ (1,0) [0|255] ""  MBMU
 SG_ I2A_Byrack_Info1_SW_Ver_Byte6 : 40|8@1+ (1,0) [0|255] ""  MBMU
 SG_ I2A_Byrack_Info1_SW_Ver_Byte7 : 48|8@1+ (1,0) [0|255] ""  MBMU
 SG_ I2A_Byrack_Info1_SW_Ver_Byte8 : 56|8@1+ (1,0) [0|255] ""  MBMU

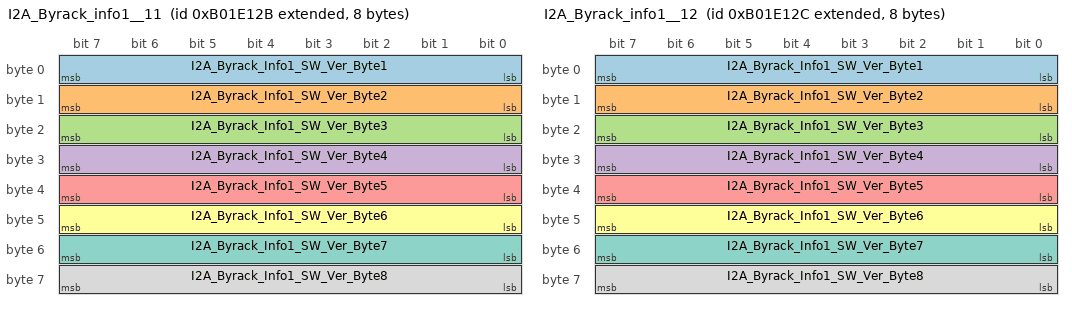
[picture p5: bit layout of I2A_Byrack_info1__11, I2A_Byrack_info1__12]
BO_ 2332156203 I2A_Byrack_info1__11: 8 IMM
 SG_ I2A_Byrack_Info1_SW_Ver_Byte1 : 0|8@1+ (1,0) [0|255] ""  MBMU
 SG_ I2A_Byrack_Info1_SW_Ver_Byte2 : 8|8@1+ (1,0) [0|255] ""  MBMU
 SG_ I2A_Byrack_Info1_SW_Ver_Byte3 : 16|8@1+ (1,0) [0|255] ""  MBMU
 SG_ I2A_Byrack_Info1_SW_Ver_Byte4 : 24|8@1+ (1,0) [0|255] ""  MBMU
 SG_ I2A_Byrack_Info1_SW_Ver_Byte5 : 32|8@1+ (1,0) [0|255] ""  MBMU
 SG_ I2A_Byrack_Info1_SW_Ver_Byte6 : 40|8@1+ (1,0) [0|255] ""  MBMU
 SG_ I2A_Byrack_Info1_SW_Ver_Byte7 : 48|8@1+ (1,0) [0|255] ""  MBMU
 SG_ I2A_Byrack_Info1_SW_Ver_Byte8 : 56|8@1+ (1,0) [0|255] ""  MBMU

BO_ 2332156204 I2A_Byrack_info1__12: 8 IMM
 SG_ I2A_Byrack_Info1_SW_Ver_Byte1 : 0|8@1+ (1,0) [0|255] ""  MBMU
 SG_ I2A_Byrack_Info1_SW_Ver_Byte2 : 8|8@1+ (1,0) [0|255] ""  MBMU
 SG_ I2A_Byrack_Info1_SW_Ver_Byte3 : 16|8@1+ (1,0) [0|255] ""  MBMU
 SG_ I2A_Byrack_Info1_SW_Ver_Byte4 : 24|8@1+ (1,0) [0|255] ""  MBMU
 SG_ I2A_Byrack_Info1_SW_Ver_Byte5 : 32|8@1+ (1,0) [0|255] ""  MBMU
 SG_ I2A_Byrack_Info1_SW_Ver_Byte6 : 40|8@1+ (1,0) [0|255] ""  MBMU
 SG_ I2A_Byrack_Info1_SW_Ver_Byte7 : 48|8@1+ (1,0) [0|255] ""  MBMU
 SG_ I2A_Byrack_Info1_SW_Ver_Byte8 : 56|8@1+ (1,0) [0|255] ""  MBMU

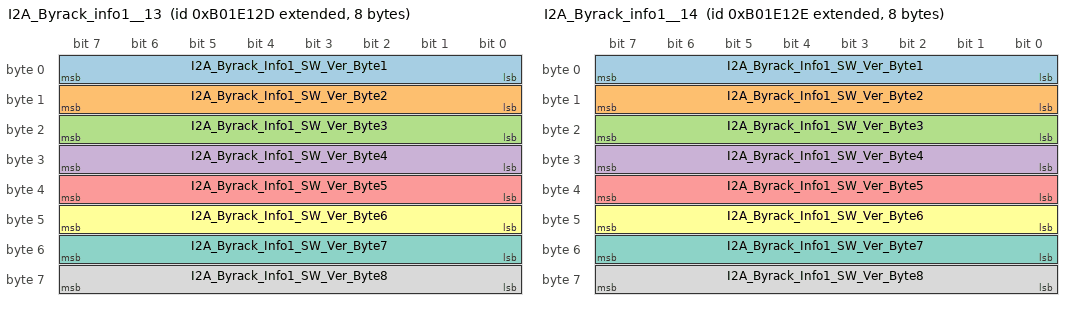
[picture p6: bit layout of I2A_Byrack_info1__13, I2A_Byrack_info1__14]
BO_ 2332156205 I2A_Byrack_info1__13: 8 IMM
 SG_ I2A_Byrack_Info1_SW_Ver_Byte1 : 0|8@1+ (1,0) [0|255] ""  MBMU
 SG_ I2A_Byrack_Info1_SW_Ver_Byte2 : 8|8@1+ (1,0) [0|255] ""  MBMU
 SG_ I2A_Byrack_Info1_SW_Ver_Byte3 : 16|8@1+ (1,0) [0|255] ""  MBMU
 SG_ I2A_Byrack_Info1_SW_Ver_Byte4 : 24|8@1+ (1,0) [0|255] ""  MBMU
 SG_ I2A_Byrack_Info1_SW_Ver_Byte5 : 32|8@1+ (1,0) [0|255] ""  MBMU
 SG_ I2A_Byrack_Info1_SW_Ver_Byte6 : 40|8@1+ (1,0) [0|255] ""  MBMU
 SG_ I2A_Byrack_Info1_SW_Ver_Byte7 : 48|8@1+ (1,0) [0|255] ""  MBMU
 SG_ I2A_Byrack_Info1_SW_Ver_Byte8 : 56|8@1+ (1,0) [0|255] ""  MBMU

BO_ 2332156206 I2A_Byrack_info1__14: 8 IMM
 SG_ I2A_Byrack_Info1_SW_Ver_Byte1 : 0|8@1+ (1,0) [0|255] ""  MBMU
 SG_ I2A_Byrack_Info1_SW_Ver_Byte2 : 8|8@1+ (1,0) [0|255] ""  MBMU
 SG_ I2A_Byrack_Info1_SW_Ver_Byte3 : 16|8@1+ (1,0) [0|255] ""  MBMU
 SG_ I2A_Byrack_Info1_SW_Ver_Byte4 : 24|8@1+ (1,0) [0|255] ""  MBMU
 SG_ I2A_Byrack_Info1_SW_Ver_Byte5 : 32|8@1+ (1,0) [0|255] ""  MBMU
 SG_ I2A_Byrack_Info1_SW_Ver_Byte6 : 40|8@1+ (1,0) [0|255] ""  MBMU
 SG_ I2A_Byrack_Info1_SW_Ver_Byte7 : 48|8@1+ (1,0) [0|255] ""  MBMU
 SG_ I2A_Byrack_Info1_SW_Ver_Byte8 : 56|8@1+ (1,0) [0|255] ""  MBMU

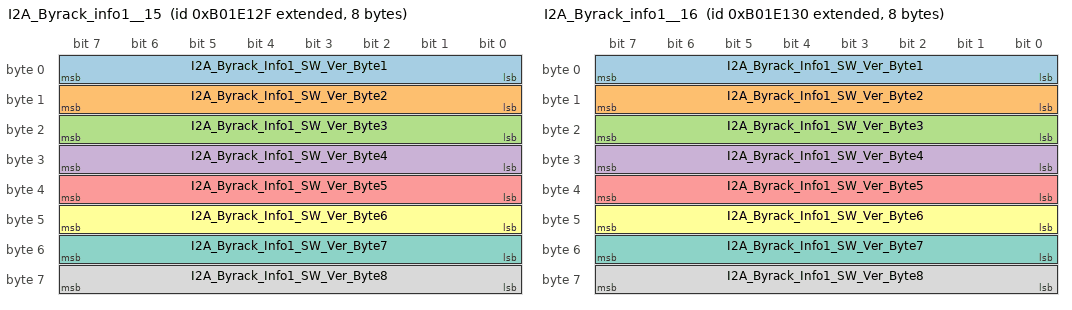
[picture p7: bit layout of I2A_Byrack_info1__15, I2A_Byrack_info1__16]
BO_ 2332156207 I2A_Byrack_info1__15: 8 IMM
 SG_ I2A_Byrack_Info1_SW_Ver_Byte1 : 0|8@1+ (1,0) [0|255] ""  MBMU
 SG_ I2A_Byrack_Info1_SW_Ver_Byte2 : 8|8@1+ (1,0) [0|255] ""  MBMU
 SG_ I2A_Byrack_Info1_SW_Ver_Byte3 : 16|8@1+ (1,0) [0|255] ""  MBMU
 SG_ I2A_Byrack_Info1_SW_Ver_Byte4 : 24|8@1+ (1,0) [0|255] ""  MBMU
 SG_ I2A_Byrack_Info1_SW_Ver_Byte5 : 32|8@1+ (1,0) [0|255] ""  MBMU
 SG_ I2A_Byrack_Info1_SW_Ver_Byte6 : 40|8@1+ (1,0) [0|255] ""  MBMU
 SG_ I2A_Byrack_Info1_SW_Ver_Byte7 : 48|8@1+ (1,0) [0|255] ""  MBMU
 SG_ I2A_Byrack_Info1_SW_Ver_Byte8 : 56|8@1+ (1,0) [0|255] ""  MBMU

BO_ 2332156208 I2A_Byrack_info1__16: 8 IMM
 SG_ I2A_Byrack_Info1_SW_Ver_Byte1 : 0|8@1+ (1,0) [0|255] ""  MBMU
 SG_ I2A_Byrack_Info1_SW_Ver_Byte2 : 8|8@1+ (1,0) [0|255] ""  MBMU
 SG_ I2A_Byrack_Info1_SW_Ver_Byte3 : 16|8@1+ (1,0) [0|255] ""  MBMU
 SG_ I2A_Byrack_Info1_SW_Ver_Byte4 : 24|8@1+ (1,0) [0|255] ""  MBMU
 SG_ I2A_Byrack_Info1_SW_Ver_Byte5 : 32|8@1+ (1,0) [0|255] ""  MBMU
 SG_ I2A_Byrack_Info1_SW_Ver_Byte6 : 40|8@1+ (1,0) [0|255] ""  MBMU
 SG_ I2A_Byrack_Info1_SW_Ver_Byte7 : 48|8@1+ (1,0) [0|255] ""  MBMU
 SG_ I2A_Byrack_Info1_SW_Ver_Byte8 : 56|8@1+ (1,0) [0|255] ""  MBMU

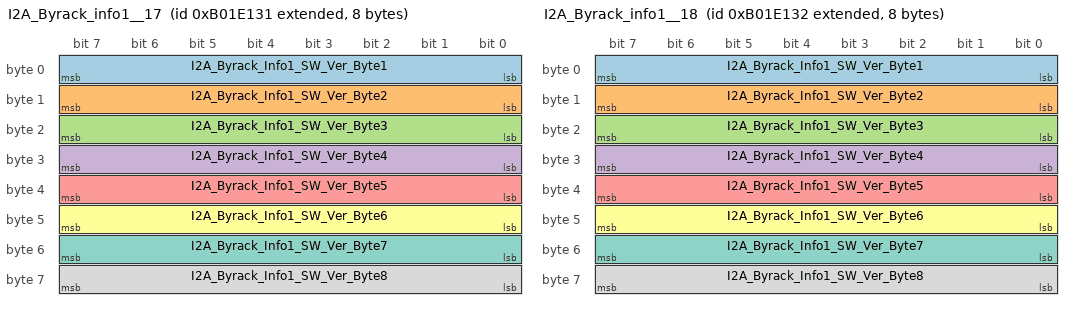
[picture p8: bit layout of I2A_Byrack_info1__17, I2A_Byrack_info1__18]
BO_ 2332156209 I2A_Byrack_info1__17: 8 IMM
 SG_ I2A_Byrack_Info1_SW_Ver_Byte1 : 0|8@1+ (1,0) [0|255] ""  MBMU
 SG_ I2A_Byrack_Info1_SW_Ver_Byte2 : 8|8@1+ (1,0) [0|255] ""  MBMU
 SG_ I2A_Byrack_Info1_SW_Ver_Byte3 : 16|8@1+ (1,0) [0|255] ""  MBMU
 SG_ I2A_Byrack_Info1_SW_Ver_Byte4 : 24|8@1+ (1,0) [0|255] ""  MBMU
 SG_ I2A_Byrack_Info1_SW_Ver_Byte5 : 32|8@1+ (1,0) [0|255] ""  MBMU
 SG_ I2A_Byrack_Info1_SW_Ver_Byte6 : 40|8@1+ (1,0) [0|255] ""  MBMU
 SG_ I2A_Byrack_Info1_SW_Ver_Byte7 : 48|8@1+ (1,0) [0|255] ""  MBMU
 SG_ I2A_Byrack_Info1_SW_Ver_Byte8 : 56|8@1+ (1,0) [0|255] ""  MBMU

BO_ 2332156210 I2A_Byrack_info1__18: 8 IMM
 SG_ I2A_Byrack_Info1_SW_Ver_Byte1 : 0|8@1+ (1,0) [0|255] ""  MBMU
 SG_ I2A_Byrack_Info1_SW_Ver_Byte2 : 8|8@1+ (1,0) [0|255] ""  MBMU
 SG_ I2A_Byrack_Info1_SW_Ver_Byte3 : 16|8@1+ (1,0) [0|255] ""  MBMU
 SG_ I2A_Byrack_Info1_SW_Ver_Byte4 : 24|8@1+ (1,0) [0|255] ""  MBMU
 SG_ I2A_Byrack_Info1_SW_Ver_Byte5 : 32|8@1+ (1,0) [0|255] ""  MBMU
 SG_ I2A_Byrack_Info1_SW_Ver_Byte6 : 40|8@1+ (1,0) [0|255] ""  MBMU
 SG_ I2A_Byrack_Info1_SW_Ver_Byte7 : 48|8@1+ (1,0) [0|255] ""  MBMU
 SG_ I2A_Byrack_Info1_SW_Ver_Byte8 : 56|8@1+ (1,0) [0|255] ""  MBMU

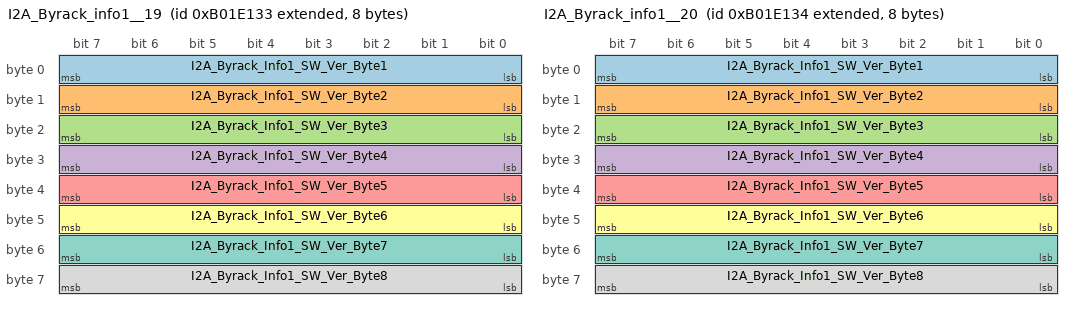
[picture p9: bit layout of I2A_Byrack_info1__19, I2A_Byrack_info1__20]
BO_ 2332156211 I2A_Byrack_info1__19: 8 IMM
 SG_ I2A_Byrack_Info1_SW_Ver_Byte1 : 0|8@1+ (1,0) [0|255] ""  MBMU
 SG_ I2A_Byrack_Info1_SW_Ver_Byte2 : 8|8@1+ (1,0) [0|255] ""  MBMU
 SG_ I2A_Byrack_Info1_SW_Ver_Byte3 : 16|8@1+ (1,0) [0|255] ""  MBMU
 SG_ I2A_Byrack_Info1_SW_Ver_Byte4 : 24|8@1+ (1,0) [0|255] ""  MBMU
 SG_ I2A_Byrack_Info1_SW_Ver_Byte5 : 32|8@1+ (1,0) [0|255] ""  MBMU
 SG_ I2A_Byrack_Info1_SW_Ver_Byte6 : 40|8@1+ (1,0) [0|255] ""  MBMU
 SG_ I2A_Byrack_Info1_SW_Ver_Byte7 : 48|8@1+ (1,0) [0|255] ""  MBMU
 SG_ I2A_Byrack_Info1_SW_Ver_Byte8 : 56|8@1+ (1,0) [0|255] ""  MBMU

BO_ 2332156212 I2A_Byrack_info1__20: 8 IMM
 SG_ I2A_Byrack_Info1_SW_Ver_Byte1 : 0|8@1+ (1,0) [0|255] ""  MBMU
 SG_ I2A_Byrack_Info1_SW_Ver_Byte2 : 8|8@1+ (1,0) [0|255] ""  MBMU
 SG_ I2A_Byrack_Info1_SW_Ver_Byte3 : 16|8@1+ (1,0) [0|255] ""  MBMU
 SG_ I2A_Byrack_Info1_SW_Ver_Byte4 : 24|8@1+ (1,0) [0|255] ""  MBMU
 SG_ I2A_Byrack_Info1_SW_Ver_Byte5 : 32|8@1+ (1,0) [0|255] ""  MBMU
 SG_ I2A_Byrack_Info1_SW_Ver_Byte6 : 40|8@1+ (1,0) [0|255] ""  MBMU
 SG_ I2A_Byrack_Info1_SW_Ver_Byte7 : 48|8@1+ (1,0) [0|255] ""  MBMU
 SG_ I2A_Byrack_Info1_SW_Ver_Byte8 : 56|8@1+ (1,0) [0|255] ""  MBMU

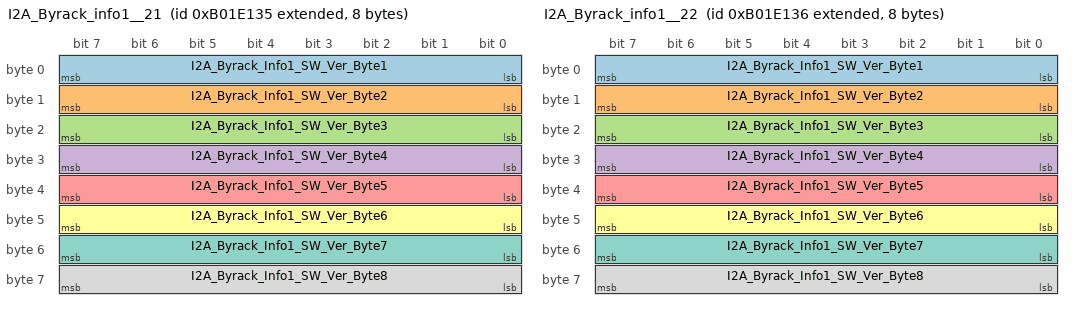
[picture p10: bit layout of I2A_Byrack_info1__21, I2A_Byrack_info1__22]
BO_ 2332156213 I2A_Byrack_info1__21: 8 IMM
 SG_ I2A_Byrack_Info1_SW_Ver_Byte1 : 0|8@1+ (1,0) [0|255] ""  MBMU
 SG_ I2A_Byrack_Info1_SW_Ver_Byte2 : 8|8@1+ (1,0) [0|255] ""  MBMU
 SG_ I2A_Byrack_Info1_SW_Ver_Byte3 : 16|8@1+ (1,0) [0|255] ""  MBMU
 SG_ I2A_Byrack_Info1_SW_Ver_Byte4 : 24|8@1+ (1,0) [0|255] ""  MBMU
 SG_ I2A_Byrack_Info1_SW_Ver_Byte5 : 32|8@1+ (1,0) [0|255] ""  MBMU
 SG_ I2A_Byrack_Info1_SW_Ver_Byte6 : 40|8@1+ (1,0) [0|255] ""  MBMU
 SG_ I2A_Byrack_Info1_SW_Ver_Byte7 : 48|8@1+ (1,0) [0|255] ""  MBMU
 SG_ I2A_Byrack_Info1_SW_Ver_Byte8 : 56|8@1+ (1,0) [0|255] ""  MBMU

BO_ 2332156214 I2A_Byrack_info1__22: 8 IMM
 SG_ I2A_Byrack_Info1_SW_Ver_Byte1 : 0|8@1+ (1,0) [0|255] ""  MBMU
 SG_ I2A_Byrack_Info1_SW_Ver_Byte2 : 8|8@1+ (1,0) [0|255] ""  MBMU
 SG_ I2A_Byrack_Info1_SW_Ver_Byte3 : 16|8@1+ (1,0) [0|255] ""  MBMU
 SG_ I2A_Byrack_Info1_SW_Ver_Byte4 : 24|8@1+ (1,0) [0|255] ""  MBMU
 SG_ I2A_Byrack_Info1_SW_Ver_Byte5 : 32|8@1+ (1,0) [0|255] ""  MBMU
 SG_ I2A_Byrack_Info1_SW_Ver_Byte6 : 40|8@1+ (1,0) [0|255] ""  MBMU
 SG_ I2A_Byrack_Info1_SW_Ver_Byte7 : 48|8@1+ (1,0) [0|255] ""  MBMU
 SG_ I2A_Byrack_Info1_SW_Ver_Byte8 : 56|8@1+ (1,0) [0|255] ""  MBMU

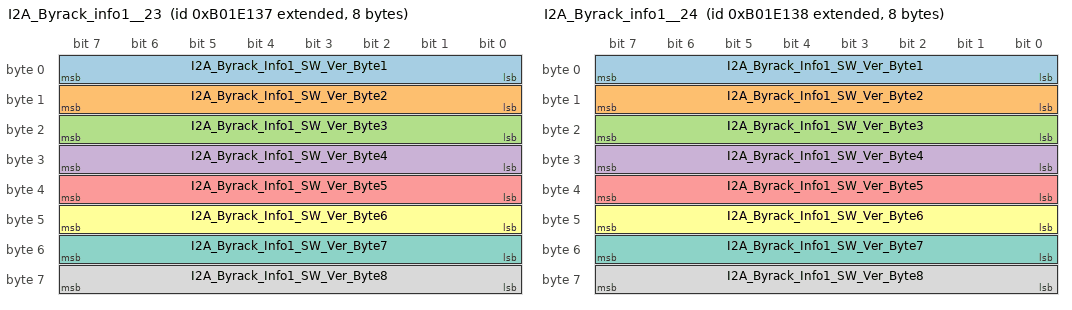
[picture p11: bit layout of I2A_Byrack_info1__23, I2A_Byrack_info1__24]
BO_ 2332156215 I2A_Byrack_info1__23: 8 IMM
 SG_ I2A_Byrack_Info1_SW_Ver_Byte1 : 0|8@1+ (1,0) [0|255] ""  MBMU
 SG_ I2A_Byrack_Info1_SW_Ver_Byte2 : 8|8@1+ (1,0) [0|255] ""  MBMU
 SG_ I2A_Byrack_Info1_SW_Ver_Byte3 : 16|8@1+ (1,0) [0|255] ""  MBMU
 SG_ I2A_Byrack_Info1_SW_Ver_Byte4 : 24|8@1+ (1,0) [0|255] ""  MBMU
 SG_ I2A_Byrack_Info1_SW_Ver_Byte5 : 32|8@1+ (1,0) [0|255] ""  MBMU
 SG_ I2A_Byrack_Info1_SW_Ver_Byte6 : 40|8@1+ (1,0) [0|255] ""  MBMU
 SG_ I2A_Byrack_Info1_SW_Ver_Byte7 : 48|8@1+ (1,0) [0|255] ""  MBMU
 SG_ I2A_Byrack_Info1_SW_Ver_Byte8 : 56|8@1+ (1,0) [0|255] ""  MBMU

BO_ 2332156216 I2A_Byrack_info1__24: 8 IMM
 SG_ I2A_Byrack_Info1_SW_Ver_Byte1 : 0|8@1+ (1,0) [0|255] ""  MBMU
 SG_ I2A_Byrack_Info1_SW_Ver_Byte2 : 8|8@1+ (1,0) [0|255] ""  MBMU
 SG_ I2A_Byrack_Info1_SW_Ver_Byte3 : 16|8@1+ (1,0) [0|255] ""  MBMU
 SG_ I2A_Byrack_Info1_SW_Ver_Byte4 : 24|8@1+ (1,0) [0|255] ""  MBMU
 SG_ I2A_Byrack_Info1_SW_Ver_Byte5 : 32|8@1+ (1,0) [0|255] ""  MBMU
 SG_ I2A_Byrack_Info1_SW_Ver_Byte6 : 40|8@1+ (1,0) [0|255] ""  MBMU
 SG_ I2A_Byrack_Info1_SW_Ver_Byte7 : 48|8@1+ (1,0) [0|255] ""  MBMU
 SG_ I2A_Byrack_Info1_SW_Ver_Byte8 : 56|8@1+ (1,0) [0|255] ""  MBMU

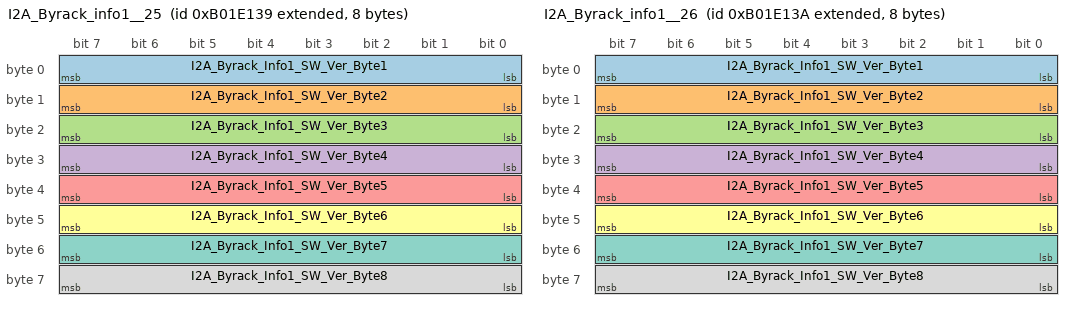
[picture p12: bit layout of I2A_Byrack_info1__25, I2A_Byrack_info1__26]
BO_ 2332156217 I2A_Byrack_info1__25: 8 IMM
 SG_ I2A_Byrack_Info1_SW_Ver_Byte1 : 0|8@1+ (1,0) [0|255] ""  MBMU
 SG_ I2A_Byrack_Info1_SW_Ver_Byte2 : 8|8@1+ (1,0) [0|255] ""  MBMU
 SG_ I2A_Byrack_Info1_SW_Ver_Byte3 : 16|8@1+ (1,0) [0|255] ""  MBMU
 SG_ I2A_Byrack_Info1_SW_Ver_Byte4 : 24|8@1+ (1,0) [0|255] ""  MBMU
 SG_ I2A_Byrack_Info1_SW_Ver_Byte5 : 32|8@1+ (1,0) [0|255] ""  MBMU
 SG_ I2A_Byrack_Info1_SW_Ver_Byte6 : 40|8@1+ (1,0) [0|255] ""  MBMU
 SG_ I2A_Byrack_Info1_SW_Ver_Byte7 : 48|8@1+ (1,0) [0|255] ""  MBMU
 SG_ I2A_Byrack_Info1_SW_Ver_Byte8 : 56|8@1+ (1,0) [0|255] ""  MBMU

BO_ 2332156218 I2A_Byrack_info1__26: 8 IMM
 SG_ I2A_Byrack_Info1_SW_Ver_Byte1 : 0|8@1+ (1,0) [0|255] ""  MBMU
 SG_ I2A_Byrack_Info1_SW_Ver_Byte2 : 8|8@1+ (1,0) [0|255] ""  MBMU
 SG_ I2A_Byrack_Info1_SW_Ver_Byte3 : 16|8@1+ (1,0) [0|255] ""  MBMU
 SG_ I2A_Byrack_Info1_SW_Ver_Byte4 : 24|8@1+ (1,0) [0|255] ""  MBMU
 SG_ I2A_Byrack_Info1_SW_Ver_Byte5 : 32|8@1+ (1,0) [0|255] ""  MBMU
 SG_ I2A_Byrack_Info1_SW_Ver_Byte6 : 40|8@1+ (1,0) [0|255] ""  MBMU
 SG_ I2A_Byrack_Info1_SW_Ver_Byte7 : 48|8@1+ (1,0) [0|255] ""  MBMU
 SG_ I2A_Byrack_Info1_SW_Ver_Byte8 : 56|8@1+ (1,0) [0|255] ""  MBMU

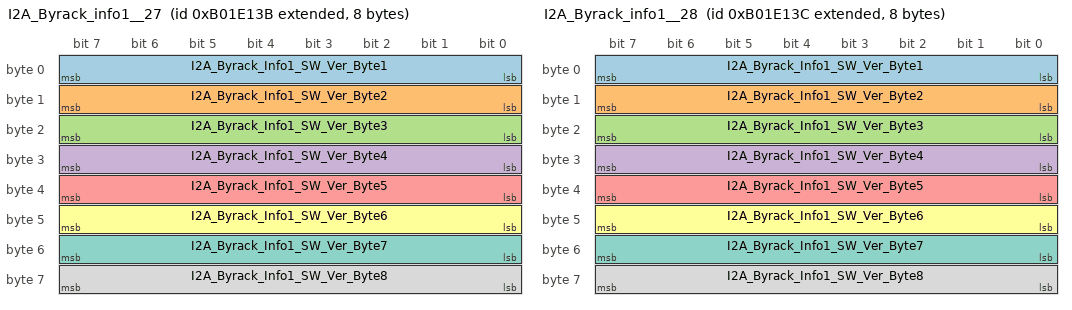
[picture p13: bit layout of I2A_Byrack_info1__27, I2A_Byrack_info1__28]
BO_ 2332156219 I2A_Byrack_info1__27: 8 IMM
 SG_ I2A_Byrack_Info1_SW_Ver_Byte1 : 0|8@1+ (1,0) [0|255] ""  MBMU
 SG_ I2A_Byrack_Info1_SW_Ver_Byte2 : 8|8@1+ (1,0) [0|255] ""  MBMU
 SG_ I2A_Byrack_Info1_SW_Ver_Byte3 : 16|8@1+ (1,0) [0|255] ""  MBMU
 SG_ I2A_Byrack_Info1_SW_Ver_Byte4 : 24|8@1+ (1,0) [0|255] ""  MBMU
 SG_ I2A_Byrack_Info1_SW_Ver_Byte5 : 32|8@1+ (1,0) [0|255] ""  MBMU
 SG_ I2A_Byrack_Info1_SW_Ver_Byte6 : 40|8@1+ (1,0) [0|255] ""  MBMU
 SG_ I2A_Byrack_Info1_SW_Ver_Byte7 : 48|8@1+ (1,0) [0|255] ""  MBMU
 SG_ I2A_Byrack_Info1_SW_Ver_Byte8 : 56|8@1+ (1,0) [0|255] ""  MBMU

BO_ 2332156220 I2A_Byrack_info1__28: 8 IMM
 SG_ I2A_Byrack_Info1_SW_Ver_Byte1 : 0|8@1+ (1,0) [0|255] ""  MBMU
 SG_ I2A_Byrack_Info1_SW_Ver_Byte2 : 8|8@1+ (1,0) [0|255] ""  MBMU
 SG_ I2A_Byrack_Info1_SW_Ver_Byte3 : 16|8@1+ (1,0) [0|255] ""  MBMU
 SG_ I2A_Byrack_Info1_SW_Ver_Byte4 : 24|8@1+ (1,0) [0|255] ""  MBMU
 SG_ I2A_Byrack_Info1_SW_Ver_Byte5 : 32|8@1+ (1,0) [0|255] ""  MBMU
 SG_ I2A_Byrack_Info1_SW_Ver_Byte6 : 40|8@1+ (1,0) [0|255] ""  MBMU
 SG_ I2A_Byrack_Info1_SW_Ver_Byte7 : 48|8@1+ (1,0) [0|255] ""  MBMU
 SG_ I2A_Byrack_Info1_SW_Ver_Byte8 : 56|8@1+ (1,0) [0|255] ""  MBMU

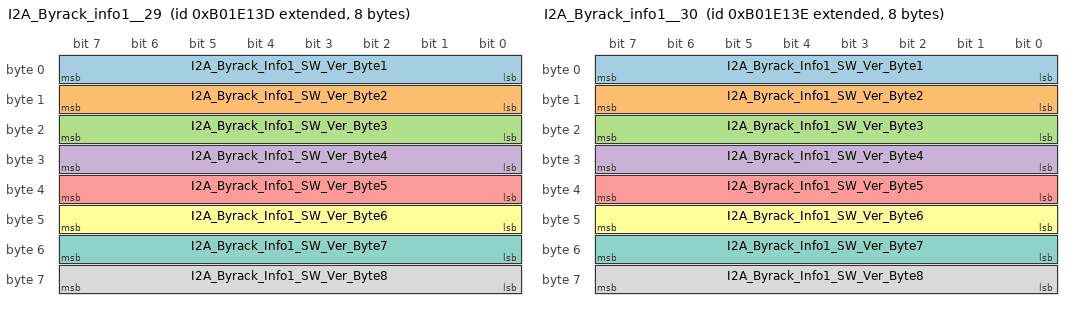
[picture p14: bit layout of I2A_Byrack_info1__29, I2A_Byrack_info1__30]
BO_ 2332156221 I2A_Byrack_info1__29: 8 IMM
 SG_ I2A_Byrack_Info1_SW_Ver_Byte1 : 0|8@1+ (1,0) [0|255] ""  MBMU
 SG_ I2A_Byrack_Info1_SW_Ver_Byte2 : 8|8@1+ (1,0) [0|255] ""  MBMU
 SG_ I2A_Byrack_Info1_SW_Ver_Byte3 : 16|8@1+ (1,0) [0|255] ""  MBMU
 SG_ I2A_Byrack_Info1_SW_Ver_Byte4 : 24|8@1+ (1,0) [0|255] ""  MBMU
 SG_ I2A_Byrack_Info1_SW_Ver_Byte5 : 32|8@1+ (1,0) [0|255] ""  MBMU
 SG_ I2A_Byrack_Info1_SW_Ver_Byte6 : 40|8@1+ (1,0) [0|255] ""  MBMU
 SG_ I2A_Byrack_Info1_SW_Ver_Byte7 : 48|8@1+ (1,0) [0|255] ""  MBMU
 SG_ I2A_Byrack_Info1_SW_Ver_Byte8 : 56|8@1+ (1,0) [0|255] ""  MBMU

BO_ 2332156222 I2A_Byrack_info1__30: 8 IMM
 SG_ I2A_Byrack_Info1_SW_Ver_Byte1 : 0|8@1+ (1,0) [0|255] ""  MBMU
 SG_ I2A_Byrack_Info1_SW_Ver_Byte2 : 8|8@1+ (1,0) [0|255] ""  MBMU
 SG_ I2A_Byrack_Info1_SW_Ver_Byte3 : 16|8@1+ (1,0) [0|255] ""  MBMU
 SG_ I2A_Byrack_Info1_SW_Ver_Byte4 : 24|8@1+ (1,0) [0|255] ""  MBMU
 SG_ I2A_Byrack_Info1_SW_Ver_Byte5 : 32|8@1+ (1,0) [0|255] ""  MBMU
 SG_ I2A_Byrack_Info1_SW_Ver_Byte6 : 40|8@1+ (1,0) [0|255] ""  MBMU
 SG_ I2A_Byrack_Info1_SW_Ver_Byte7 : 48|8@1+ (1,0) [0|255] ""  MBMU
 SG_ I2A_Byrack_Info1_SW_Ver_Byte8 : 56|8@1+ (1,0) [0|255] ""  MBMU

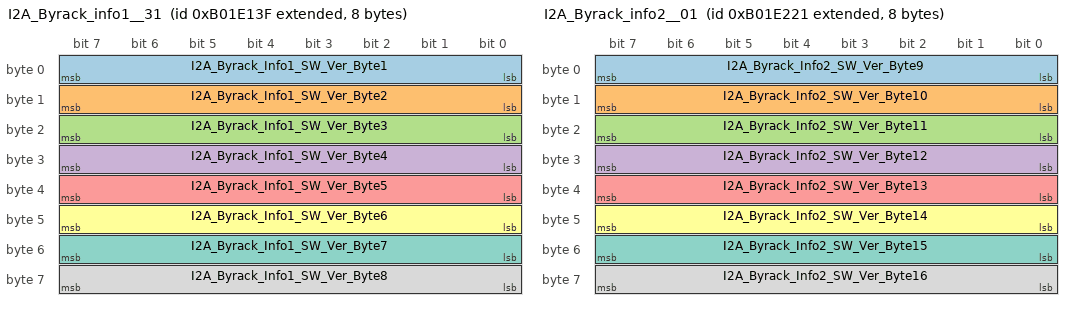
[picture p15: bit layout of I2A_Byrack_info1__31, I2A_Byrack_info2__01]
BO_ 2332156223 I2A_Byrack_info1__31: 8 IMM
 SG_ I2A_Byrack_Info1_SW_Ver_Byte1 : 0|8@1+ (1,0) [0|255] ""  MBMU
 SG_ I2A_Byrack_Info1_SW_Ver_Byte2 : 8|8@1+ (1,0) [0|255] ""  MBMU
 SG_ I2A_Byrack_Info1_SW_Ver_Byte3 : 16|8@1+ (1,0) [0|255] ""  MBMU
 SG_ I2A_Byrack_Info1_SW_Ver_Byte4 : 24|8@1+ (1,0) [0|255] ""  MBMU
 SG_ I2A_Byrack_Info1_SW_Ver_Byte5 : 32|8@1+ (1,0) [0|255] ""  MBMU
 SG_ I2A_Byrack_Info1_SW_Ver_Byte6 : 40|8@1+ (1,0) [0|255] ""  MBMU
 SG_ I2A_Byrack_Info1_SW_Ver_Byte7 : 48|8@1+ (1,0) [0|255] ""  MBMU
 SG_ I2A_Byrack_Info1_SW_Ver_Byte8 : 56|8@1+ (1,0) [0|255] ""  MBMU

BO_ 2332156449 I2A_Byrack_info2__01: 8 IMM
 SG_ I2A_Byrack_Info2_SW_Ver_Byte9 : 0|8@1+ (1,0) [0|255] ""  MBMU
 SG_ I2A_Byrack_Info2_SW_Ver_Byte10 : 8|8@1+ (1,0) [0|255] ""  MBMU
 SG_ I2A_Byrack_Info2_SW_Ver_Byte11 : 16|8@1+ (1,0) [0|255] ""  MBMU
 SG_ I2A_Byrack_Info2_SW_Ver_Byte12 : 24|8@1+ (1,0) [0|255] ""  MBMU
 SG_ I2A_Byrack_Info2_SW_Ver_Byte13 : 32|8@1+ (1,0) [0|255] ""  MBMU
 SG_ I2A_Byrack_Info2_SW_Ver_Byte14 : 40|8@1+ (1,0) [0|255] ""  MBMU
 SG_ I2A_Byrack_Info2_SW_Ver_Byte15 : 48|8@1+ (1,0) [0|255] ""  MBMU
 SG_ I2A_Byrack_Info2_SW_Ver_Byte16 : 56|8@1+ (1,0) [0|255] ""  MBMU

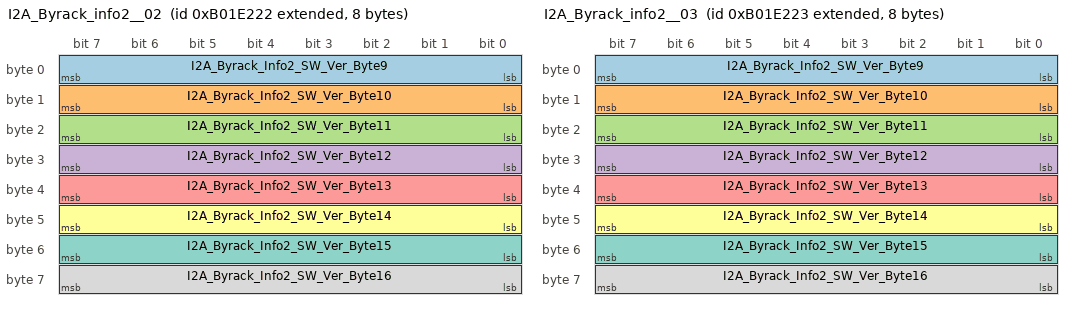
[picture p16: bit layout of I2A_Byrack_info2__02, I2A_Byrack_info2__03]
BO_ 2332156450 I2A_Byrack_info2__02: 8 IMM
 SG_ I2A_Byrack_Info2_SW_Ver_Byte9 : 0|8@1+ (1,0) [0|255] ""  MBMU
 SG_ I2A_Byrack_Info2_SW_Ver_Byte10 : 8|8@1+ (1,0) [0|255] ""  MBMU
 SG_ I2A_Byrack_Info2_SW_Ver_Byte11 : 16|8@1+ (1,0) [0|255] ""  MBMU
 SG_ I2A_Byrack_Info2_SW_Ver_Byte12 : 24|8@1+ (1,0) [0|255] ""  MBMU
 SG_ I2A_Byrack_Info2_SW_Ver_Byte13 : 32|8@1+ (1,0) [0|255] ""  MBMU
 SG_ I2A_Byrack_Info2_SW_Ver_Byte14 : 40|8@1+ (1,0) [0|255] ""  MBMU
 SG_ I2A_Byrack_Info2_SW_Ver_Byte15 : 48|8@1+ (1,0) [0|255] ""  MBMU
 SG_ I2A_Byrack_Info2_SW_Ver_Byte16 : 56|8@1+ (1,0) [0|255] ""  MBMU

BO_ 2332156451 I2A_Byrack_info2__03: 8 IMM
 SG_ I2A_Byrack_Info2_SW_Ver_Byte9 : 0|8@1+ (1,0) [0|255] ""  MBMU
 SG_ I2A_Byrack_Info2_SW_Ver_Byte10 : 8|8@1+ (1,0) [0|255] ""  MBMU
 SG_ I2A_Byrack_Info2_SW_Ver_Byte11 : 16|8@1+ (1,0) [0|255] ""  MBMU
 SG_ I2A_Byrack_Info2_SW_Ver_Byte12 : 24|8@1+ (1,0) [0|255] ""  MBMU
 SG_ I2A_Byrack_Info2_SW_Ver_Byte13 : 32|8@1+ (1,0) [0|255] ""  MBMU
 SG_ I2A_Byrack_Info2_SW_Ver_Byte14 : 40|8@1+ (1,0) [0|255] ""  MBMU
 SG_ I2A_Byrack_Info2_SW_Ver_Byte15 : 48|8@1+ (1,0) [0|255] ""  MBMU
 SG_ I2A_Byrack_Info2_SW_Ver_Byte16 : 56|8@1+ (1,0) [0|255] ""  MBMU

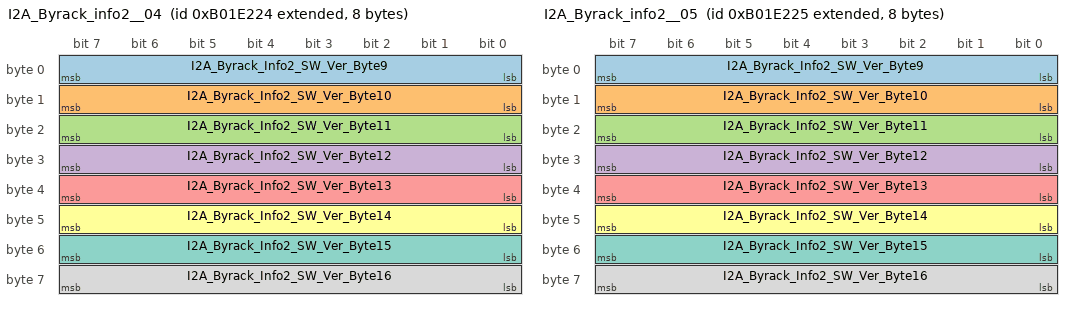
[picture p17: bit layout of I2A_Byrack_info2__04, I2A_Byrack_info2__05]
BO_ 2332156452 I2A_Byrack_info2__04: 8 IMM
 SG_ I2A_Byrack_Info2_SW_Ver_Byte9 : 0|8@1+ (1,0) [0|255] ""  MBMU
 SG_ I2A_Byrack_Info2_SW_Ver_Byte10 : 8|8@1+ (1,0) [0|255] ""  MBMU
 SG_ I2A_Byrack_Info2_SW_Ver_Byte11 : 16|8@1+ (1,0) [0|255] ""  MBMU
 SG_ I2A_Byrack_Info2_SW_Ver_Byte12 : 24|8@1+ (1,0) [0|255] ""  MBMU
 SG_ I2A_Byrack_Info2_SW_Ver_Byte13 : 32|8@1+ (1,0) [0|255] ""  MBMU
 SG_ I2A_Byrack_Info2_SW_Ver_Byte14 : 40|8@1+ (1,0) [0|255] ""  MBMU
 SG_ I2A_Byrack_Info2_SW_Ver_Byte15 : 48|8@1+ (1,0) [0|255] ""  MBMU
 SG_ I2A_Byrack_Info2_SW_Ver_Byte16 : 56|8@1+ (1,0) [0|255] ""  MBMU

BO_ 2332156453 I2A_Byrack_info2__05: 8 IMM
 SG_ I2A_Byrack_Info2_SW_Ver_Byte9 : 0|8@1+ (1,0) [0|255] ""  MBMU
 SG_ I2A_Byrack_Info2_SW_Ver_Byte10 : 8|8@1+ (1,0) [0|255] ""  MBMU
 SG_ I2A_Byrack_Info2_SW_Ver_Byte11 : 16|8@1+ (1,0) [0|255] ""  MBMU
 SG_ I2A_Byrack_Info2_SW_Ver_Byte12 : 24|8@1+ (1,0) [0|255] ""  MBMU
 SG_ I2A_Byrack_Info2_SW_Ver_Byte13 : 32|8@1+ (1,0) [0|255] ""  MBMU
 SG_ I2A_Byrack_Info2_SW_Ver_Byte14 : 40|8@1+ (1,0) [0|255] ""  MBMU
 SG_ I2A_Byrack_Info2_SW_Ver_Byte15 : 48|8@1+ (1,0) [0|255] ""  MBMU
 SG_ I2A_Byrack_Info2_SW_Ver_Byte16 : 56|8@1+ (1,0) [0|255] ""  MBMU

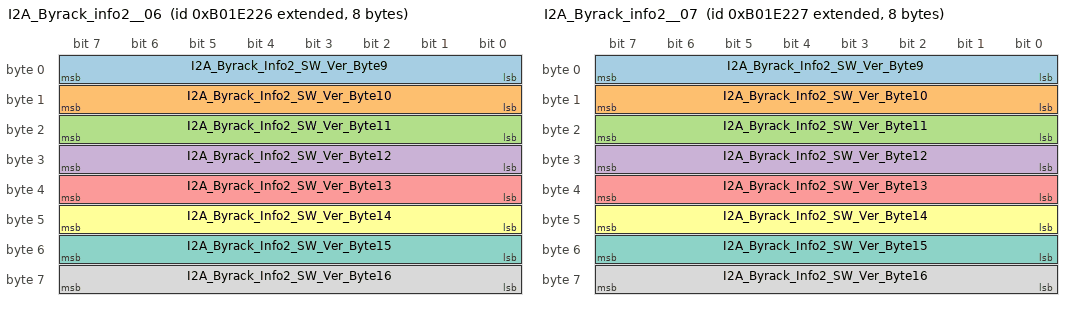
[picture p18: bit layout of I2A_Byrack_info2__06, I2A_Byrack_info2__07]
BO_ 2332156454 I2A_Byrack_info2__06: 8 IMM
 SG_ I2A_Byrack_Info2_SW_Ver_Byte9 : 0|8@1+ (1,0) [0|255] ""  MBMU
 SG_ I2A_Byrack_Info2_SW_Ver_Byte10 : 8|8@1+ (1,0) [0|255] ""  MBMU
 SG_ I2A_Byrack_Info2_SW_Ver_Byte11 : 16|8@1+ (1,0) [0|255] ""  MBMU
 SG_ I2A_Byrack_Info2_SW_Ver_Byte12 : 24|8@1+ (1,0) [0|255] ""  MBMU
 SG_ I2A_Byrack_Info2_SW_Ver_Byte13 : 32|8@1+ (1,0) [0|255] ""  MBMU
 SG_ I2A_Byrack_Info2_SW_Ver_Byte14 : 40|8@1+ (1,0) [0|255] ""  MBMU
 SG_ I2A_Byrack_Info2_SW_Ver_Byte15 : 48|8@1+ (1,0) [0|255] ""  MBMU
 SG_ I2A_Byrack_Info2_SW_Ver_Byte16 : 56|8@1+ (1,0) [0|255] ""  MBMU

BO_ 2332156455 I2A_Byrack_info2__07: 8 IMM
 SG_ I2A_Byrack_Info2_SW_Ver_Byte9 : 0|8@1+ (1,0) [0|255] ""  MBMU
 SG_ I2A_Byrack_Info2_SW_Ver_Byte10 : 8|8@1+ (1,0) [0|255] ""  MBMU
 SG_ I2A_Byrack_Info2_SW_Ver_Byte11 : 16|8@1+ (1,0) [0|255] ""  MBMU
 SG_ I2A_Byrack_Info2_SW_Ver_Byte12 : 24|8@1+ (1,0) [0|255] ""  MBMU
 SG_ I2A_Byrack_Info2_SW_Ver_Byte13 : 32|8@1+ (1,0) [0|255] ""  MBMU
 SG_ I2A_Byrack_Info2_SW_Ver_Byte14 : 40|8@1+ (1,0) [0|255] ""  MBMU
 SG_ I2A_Byrack_Info2_SW_Ver_Byte15 : 48|8@1+ (1,0) [0|255] ""  MBMU
 SG_ I2A_Byrack_Info2_SW_Ver_Byte16 : 56|8@1+ (1,0) [0|255] ""  MBMU

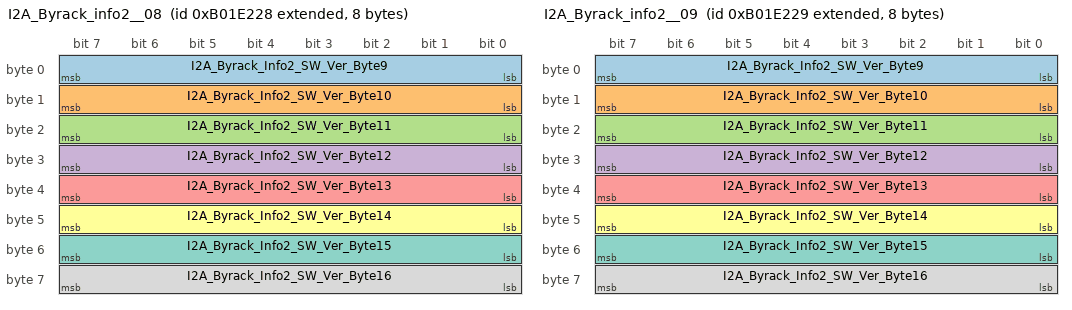
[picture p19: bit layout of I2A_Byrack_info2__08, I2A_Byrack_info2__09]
BO_ 2332156456 I2A_Byrack_info2__08: 8 IMM
 SG_ I2A_Byrack_Info2_SW_Ver_Byte9 : 0|8@1+ (1,0) [0|255] ""  MBMU
 SG_ I2A_Byrack_Info2_SW_Ver_Byte10 : 8|8@1+ (1,0) [0|255] ""  MBMU
 SG_ I2A_Byrack_Info2_SW_Ver_Byte11 : 16|8@1+ (1,0) [0|255] ""  MBMU
 SG_ I2A_Byrack_Info2_SW_Ver_Byte12 : 24|8@1+ (1,0) [0|255] ""  MBMU
 SG_ I2A_Byrack_Info2_SW_Ver_Byte13 : 32|8@1+ (1,0) [0|255] ""  MBMU
 SG_ I2A_Byrack_Info2_SW_Ver_Byte14 : 40|8@1+ (1,0) [0|255] ""  MBMU
 SG_ I2A_Byrack_Info2_SW_Ver_Byte15 : 48|8@1+ (1,0) [0|255] ""  MBMU
 SG_ I2A_Byrack_Info2_SW_Ver_Byte16 : 56|8@1+ (1,0) [0|255] ""  MBMU

BO_ 2332156457 I2A_Byrack_info2__09: 8 IMM
 SG_ I2A_Byrack_Info2_SW_Ver_Byte9 : 0|8@1+ (1,0) [0|255] ""  MBMU
 SG_ I2A_Byrack_Info2_SW_Ver_Byte10 : 8|8@1+ (1,0) [0|255] ""  MBMU
 SG_ I2A_Byrack_Info2_SW_Ver_Byte11 : 16|8@1+ (1,0) [0|255] ""  MBMU
 SG_ I2A_Byrack_Info2_SW_Ver_Byte12 : 24|8@1+ (1,0) [0|255] ""  MBMU
 SG_ I2A_Byrack_Info2_SW_Ver_Byte13 : 32|8@1+ (1,0) [0|255] ""  MBMU
 SG_ I2A_Byrack_Info2_SW_Ver_Byte14 : 40|8@1+ (1,0) [0|255] ""  MBMU
 SG_ I2A_Byrack_Info2_SW_Ver_Byte15 : 48|8@1+ (1,0) [0|255] ""  MBMU
 SG_ I2A_Byrack_Info2_SW_Ver_Byte16 : 56|8@1+ (1,0) [0|255] ""  MBMU

BO_ 2332156458 I2A_Byrack_info2__10: 8 IMM
 SG_ I2A_Byrack_Info2_SW_Ver_Byte9 : 0|8@1+ (1,0) [0|255] ""  MBMU
 SG_ I2A_Byrack_Info2_SW_Ver_Byte10 : 8|8@1+ (1,0) [0|255] ""  MBMU
 SG_ I2A_Byrack_Info2_SW_Ver_Byte11 : 16|8@1+ (1,0) [0|255] ""  MBMU
 SG_ I2A_Byrack_Info2_SW_Ver_Byte12 : 24|8@1+ (1,0) [0|255] ""  MBMU
 SG_ I2A_Byrack_Info2_SW_Ver_Byte13 : 32|8@1+ (1,0) [0|255] ""  MBMU
 SG_ I2A_Byrack_Info2_SW_Ver_Byte14 : 40|8@1+ (1,0) [0|255] ""  MBMU
 SG_ I2A_Byrack_Info2_SW_Ver_Byte15 : 48|8@1+ (1,0) [0|255] ""  MBMU
 SG_ I2A_Byrack_Info2_SW_Ver_Byte16 : 56|8@1+ (1,0) [0|255] ""  MBMU

BO_ 2332156459 I2A_Byrack_info2__11: 8 IMM
 SG_ I2A_Byrack_Info2_SW_Ver_Byte9 : 0|8@1+ (1,0) [0|255] ""  MBMU
 SG_ I2A_Byrack_Info2_SW_Ver_Byte10 : 8|8@1+ (1,0) [0|255] ""  MBMU
 SG_ I2A_Byrack_Info2_SW_Ver_Byte11 : 16|8@1+ (1,0) [0|255] ""  MBMU
 SG_ I2A_Byrack_Info2_SW_Ver_Byte12 : 24|8@1+ (1,0) [0|255] ""  MBMU
 SG_ I2A_Byrack_Info2_SW_Ver_Byte13 : 32|8@1+ (1,0) [0|255] ""  MBMU
 SG_ I2A_Byrack_Info2_SW_Ver_Byte14 : 40|8@1+ (1,0) [0|255] ""  MBMU
 SG_ I2A_Byrack_Info2_SW_Ver_Byte15 : 48|8@1+ (1,0) [0|255] ""  MBMU
 SG_ I2A_Byrack_Info2_SW_Ver_Byte16 : 56|8@1+ (1,0) [0|255] ""  MBMU

BO_ 2332156460 I2A_Byrack_info2__12: 8 IMM
 SG_ I2A_Byrack_Info2_SW_Ver_Byte9 : 0|8@1+ (1,0) [0|255] ""  MBMU
 SG_ I2A_Byrack_Info2_SW_Ver_Byte10 : 8|8@1+ (1,0) [0|255] ""  MBMU
 SG_ I2A_Byrack_Info2_SW_Ver_Byte11 : 16|8@1+ (1,0) [0|255] ""  MBMU
 SG_ I2A_Byrack_Info2_SW_Ver_Byte12 : 24|8@1+ (1,0) [0|255] ""  MBMU
 SG_ I2A_Byrack_Info2_SW_Ver_Byte13 : 32|8@1+ (1,0) [0|255] ""  MBMU
 SG_ I2A_Byrack_Info2_SW_Ver_Byte14 : 40|8@1+ (1,0) [0|255] ""  MBMU
 SG_ I2A_Byrack_Info2_SW_Ver_Byte15 : 48|8@1+ (1,0) [0|255] ""  MBMU
 SG_ I2A_Byrack_Info2_SW_Ver_Byte16 : 56|8@1+ (1,0) [0|255] ""  MBMU

BO_ 2332156461 I2A_Byrack_info2__13: 8 IMM
 SG_ I2A_Byrack_Info2_SW_Ver_Byte9 : 0|8@1+ (1,0) [0|255] ""  MBMU
 SG_ I2A_Byrack_Info2_SW_Ver_Byte10 : 8|8@1+ (1,0) [0|255] ""  MBMU
 SG_ I2A_Byrack_Info2_SW_Ver_Byte11 : 16|8@1+ (1,0) [0|255] ""  MBMU
 SG_ I2A_Byrack_Info2_SW_Ver_Byte12 : 24|8@1+ (1,0) [0|255] ""  MBMU
 SG_ I2A_Byrack_Info2_SW_Ver_Byte13 : 32|8@1+ (1,0) [0|255] ""  MBMU
 SG_ I2A_Byrack_Info2_SW_Ver_Byte14 : 40|8@1+ (1,0) [0|255] ""  MBMU
 SG_ I2A_Byrack_Info2_SW_Ver_Byte15 : 48|8@1+ (1,0) [0|255] ""  MBMU
 SG_ I2A_Byrack_Info2_SW_Ver_Byte16 : 56|8@1+ (1,0) [0|255] ""  MBMU

BO_ 2332156462 I2A_Byrack_info2__14: 8 IMM
 SG_ I2A_Byrack_Info2_SW_Ver_Byte9 : 0|8@1+ (1,0) [0|255] ""  MBMU
 SG_ I2A_Byrack_Info2_SW_Ver_Byte10 : 8|8@1+ (1,0) [0|255] ""  MBMU
 SG_ I2A_Byrack_Info2_SW_Ver_Byte11 : 16|8@1+ (1,0) [0|255] ""  MBMU
 SG_ I2A_Byrack_Info2_SW_Ver_Byte12 : 24|8@1+ (1,0) [0|255] ""  MBMU
 SG_ I2A_Byrack_Info2_SW_Ver_Byte13 : 32|8@1+ (1,0) [0|255] ""  MBMU
 SG_ I2A_Byrack_Info2_SW_Ver_Byte14 : 40|8@1+ (1,0) [0|255] ""  MBMU
 SG_ I2A_Byrack_Info2_SW_Ver_Byte15 : 48|8@1+ (1,0) [0|255] ""  MBMU
 SG_ I2A_Byrack_Info2_SW_Ver_Byte16 : 56|8@1+ (1,0) [0|255] ""  MBMU

BO_ 2332156463 I2A_Byrack_info2__15: 8 IMM
 SG_ I2A_Byrack_Info2_SW_Ver_Byte9 : 0|8@1+ (1,0) [0|255] ""  MBMU
 SG_ I2A_Byrack_Info2_SW_Ver_Byte10 : 8|8@1+ (1,0) [0|255] ""  MBMU
 SG_ I2A_Byrack_Info2_SW_Ver_Byte11 : 16|8@1+ (1,0) [0|255] ""  MBMU
 SG_ I2A_Byrack_Info2_SW_Ver_Byte12 : 24|8@1+ (1,0) [0|255] ""  MBMU
 SG_ I2A_Byrack_Info2_SW_Ver_Byte13 : 32|8@1+ (1,0) [0|255] ""  MBMU
 SG_ I2A_Byrack_Info2_SW_Ver_Byte14 : 40|8@1+ (1,0) [0|255] ""  MBMU
 SG_ I2A_Byrack_Info2_SW_Ver_Byte15 : 48|8@1+ (1,0) [0|255] ""  MBMU
 SG_ I2A_Byrack_Info2_SW_Ver_Byte16 : 56|8@1+ (1,0) [0|255] ""  MBMU

BO_ 2332156464 I2A_Byrack_info2__16: 8 IMM
 SG_ I2A_Byrack_Info2_SW_Ver_Byte9 : 0|8@1+ (1,0) [0|255] ""  MBMU
 SG_ I2A_Byrack_Info2_SW_Ver_Byte10 : 8|8@1+ (1,0) [0|255] ""  MBMU
 SG_ I2A_Byrack_Info2_SW_Ver_Byte11 : 16|8@1+ (1,0) [0|255] ""  MBMU
 SG_ I2A_Byrack_Info2_SW_Ver_Byte12 : 24|8@1+ (1,0) [0|255] ""  MBMU
 SG_ I2A_Byrack_Info2_SW_Ver_Byte13 : 32|8@1+ (1,0) [0|255] ""  MBMU
 SG_ I2A_Byrack_Info2_SW_Ver_Byte14 : 40|8@1+ (1,0) [0|255] ""  MBMU
 SG_ I2A_Byrack_Info2_SW_Ver_Byte15 : 48|8@1+ (1,0) [0|255] ""  MBMU
 SG_ I2A_Byrack_Info2_SW_Ver_Byte16 : 56|8@1+ (1,0) [0|255] ""  MBMU

BO_ 2332156465 I2A_Byrack_info2__17: 8 IMM
 SG_ I2A_Byrack_Info2_SW_Ver_Byte9 : 0|8@1+ (1,0) [0|255] ""  MBMU
 SG_ I2A_Byrack_Info2_SW_Ver_Byte10 : 8|8@1+ (1,0) [0|255] ""  MBMU
 SG_ I2A_Byrack_Info2_SW_Ver_Byte11 : 16|8@1+ (1,0) [0|255] ""  MBMU
 SG_ I2A_Byrack_Info2_SW_Ver_Byte12 : 24|8@1+ (1,0) [0|255] ""  MBMU
 SG_ I2A_Byrack_Info2_SW_Ver_Byte13 : 32|8@1+ (1,0) [0|255] ""  MBMU
 SG_ I2A_Byrack_Info2_SW_Ver_Byte14 : 40|8@1+ (1,0) [0|255] ""  MBMU
 SG_ I2A_Byrack_Info2_SW_Ver_Byte15 : 48|8@1+ (1,0) [0|255] ""  MBMU
 SG_ I2A_Byrack_Info2_SW_Ver_Byte16 : 56|8@1+ (1,0) [0|255] ""  MBMU

BO_ 2332156466 I2A_Byrack_info2__18: 8 IMM
 SG_ I2A_Byrack_Info2_SW_Ver_Byte9 : 0|8@1+ (1,0) [0|255] ""  MBMU
 SG_ I2A_Byrack_Info2_SW_Ver_Byte10 : 8|8@1+ (1,0) [0|255] ""  MBMU
 SG_ I2A_Byrack_Info2_SW_Ver_Byte11 : 16|8@1+ (1,0) [0|255] ""  MBMU
 SG_ I2A_Byrack_Info2_SW_Ver_Byte12 : 24|8@1+ (1,0) [0|255] ""  MBMU
 SG_ I2A_Byrack_Info2_SW_Ver_Byte13 : 32|8@1+ (1,0) [0|255] ""  MBMU
 SG_ I2A_Byrack_Info2_SW_Ver_Byte14 : 40|8@1+ (1,0) [0|255] ""  MBMU
 SG_ I2A_Byrack_Info2_SW_Ver_Byte15 : 48|8@1+ (1,0) [0|255] ""  MBMU
 SG_ I2A_Byrack_Info2_SW_Ver_Byte16 : 56|8@1+ (1,0) [0|255] ""  MBMU

BO_ 2332156467 I2A_Byrack_info2__19: 8 IMM
 SG_ I2A_Byrack_Info2_SW_Ver_Byte9 : 0|8@1+ (1,0) [0|255] ""  MBMU
 SG_ I2A_Byrack_Info2_SW_Ver_Byte10 : 8|8@1+ (1,0) [0|255] ""  MBMU
 SG_ I2A_Byrack_Info2_SW_Ver_Byte11 : 16|8@1+ (1,0) [0|255] ""  MBMU
 SG_ I2A_Byrack_Info2_SW_Ver_Byte12 : 24|8@1+ (1,0) [0|255] ""  MBMU
 SG_ I2A_Byrack_Info2_SW_Ver_Byte13 : 32|8@1+ (1,0) [0|255] ""  MBMU
 SG_ I2A_Byrack_Info2_SW_Ver_Byte14 : 40|8@1+ (1,0) [0|255] ""  MBMU
 SG_ I2A_Byrack_Info2_SW_Ver_Byte15 : 48|8@1+ (1,0) [0|255] ""  MBMU
 SG_ I2A_Byrack_Info2_SW_Ver_Byte16 : 56|8@1+ (1,0) [0|255] ""  MBMU

BO_ 2332156468 I2A_Byrack_info2__20: 8 IMM
 SG_ I2A_Byrack_Info2_SW_Ver_Byte9 : 0|8@1+ (1,0) [0|255] ""  MBMU
 SG_ I2A_Byrack_Info2_SW_Ver_Byte10 : 8|8@1+ (1,0) [0|255] ""  MBMU
 SG_ I2A_Byrack_Info2_SW_Ver_Byte11 : 16|8@1+ (1,0) [0|255] ""  MBMU
 SG_ I2A_Byrack_Info2_SW_Ver_Byte12 : 24|8@1+ (1,0) [0|255] ""  MBMU
 SG_ I2A_Byrack_Info2_SW_Ver_Byte13 : 32|8@1+ (1,0) [0|255] ""  MBMU
 SG_ I2A_Byrack_Info2_SW_Ver_Byte14 : 40|8@1+ (1,0) [0|255] ""  MBMU
 SG_ I2A_Byrack_Info2_SW_Ver_Byte15 : 48|8@1+ (1,0) [0|255] ""  MBMU
 SG_ I2A_Byrack_Info2_SW_Ver_Byte16 : 56|8@1+ (1,0) [0|255] ""  MBMU

BO_ 2332156469 I2A_Byrack_info2__21: 8 IMM
 SG_ I2A_Byrack_Info2_SW_Ver_Byte9 : 0|8@1+ (1,0) [0|255] ""  MBMU
 SG_ I2A_Byrack_Info2_SW_Ver_Byte10 : 8|8@1+ (1,0) [0|255] ""  MBMU
 SG_ I2A_Byrack_Info2_SW_Ver_Byte11 : 16|8@1+ (1,0) [0|255] ""  MBMU
 SG_ I2A_Byrack_Info2_SW_Ver_Byte12 : 24|8@1+ (1,0) [0|255] ""  MBMU
 SG_ I2A_Byrack_Info2_SW_Ver_Byte13 : 32|8@1+ (1,0) [0|255] ""  MBMU
 SG_ I2A_Byrack_Info2_SW_Ver_Byte14 : 40|8@1+ (1,0) [0|255] ""  MBMU
 SG_ I2A_Byrack_Info2_SW_Ver_Byte15 : 48|8@1+ (1,0) [0|255] ""  MBMU
 SG_ I2A_Byrack_Info2_SW_Ver_Byte16 : 56|8@1+ (1,0) [0|255] ""  MBMU

BO_ 2332156470 I2A_Byrack_info2__22: 8 IMM
 SG_ I2A_Byrack_Info2_SW_Ver_Byte9 : 0|8@1+ (1,0) [0|255] ""  MBMU
 SG_ I2A_Byrack_Info2_SW_Ver_Byte10 : 8|8@1+ (1,0) [0|255] ""  MBMU
 SG_ I2A_Byrack_Info2_SW_Ver_Byte11 : 16|8@1+ (1,0) [0|255] ""  MBMU
 SG_ I2A_Byrack_Info2_SW_Ver_Byte12 : 24|8@1+ (1,0) [0|255] ""  MBMU
 SG_ I2A_Byrack_Info2_SW_Ver_Byte13 : 32|8@1+ (1,0) [0|255] ""  MBMU
 SG_ I2A_Byrack_Info2_SW_Ver_Byte14 : 40|8@1+ (1,0) [0|255] ""  MBMU
 SG_ I2A_Byrack_Info2_SW_Ver_Byte15 : 48|8@1+ (1,0) [0|255] ""  MBMU
 SG_ I2A_Byrack_Info2_SW_Ver_Byte16 : 56|8@1+ (1,0) [0|255] ""  MBMU

BO_ 2332156471 I2A_Byrack_info2__23: 8 IMM
 SG_ I2A_Byrack_Info2_SW_Ver_Byte9 : 0|8@1+ (1,0) [0|255] ""  MBMU
 SG_ I2A_Byrack_Info2_SW_Ver_Byte10 : 8|8@1+ (1,0) [0|255] ""  MBMU
 SG_ I2A_Byrack_Info2_SW_Ver_Byte11 : 16|8@1+ (1,0) [0|255] ""  MBMU
 SG_ I2A_Byrack_Info2_SW_Ver_Byte12 : 24|8@1+ (1,0) [0|255] ""  MBMU
 SG_ I2A_Byrack_Info2_SW_Ver_Byte13 : 32|8@1+ (1,0) [0|255] ""  MBMU
 SG_ I2A_Byrack_Info2_SW_Ver_Byte14 : 40|8@1+ (1,0) [0|255] ""  MBMU
 SG_ I2A_Byrack_Info2_SW_Ver_Byte15 : 48|8@1+ (1,0) [0|255] ""  MBMU
 SG_ I2A_Byrack_Info2_SW_Ver_Byte16 : 56|8@1+ (1,0) [0|255] ""  MBMU

BO_ 2332156472 I2A_Byrack_info2__24: 8 IMM
 SG_ I2A_Byrack_Info2_SW_Ver_Byte9 : 0|8@1+ (1,0) [0|255] ""  MBMU
 SG_ I2A_Byrack_Info2_SW_Ver_Byte10 : 8|8@1+ (1,0) [0|255] ""  MBMU
 SG_ I2A_Byrack_Info2_SW_Ver_Byte11 : 16|8@1+ (1,0) [0|255] ""  MBMU
 SG_ I2A_Byrack_Info2_SW_Ver_Byte12 : 24|8@1+ (1,0) [0|255] ""  MBMU
 SG_ I2A_Byrack_Info2_SW_Ver_Byte13 : 32|8@1+ (1,0) [0|255] ""  MBMU
 SG_ I2A_Byrack_Info2_SW_Ver_Byte14 : 40|8@1+ (1,0) [0|255] ""  MBMU
 SG_ I2A_Byrack_Info2_SW_Ver_Byte15 : 48|8@1+ (1,0) [0|255] ""  MBMU
 SG_ I2A_Byrack_Info2_SW_Ver_Byte16 : 56|8@1+ (1,0) [0|255] ""  MBMU

BO_ 2332156473 I2A_Byrack_info2__25: 8 IMM
 SG_ I2A_Byrack_Info2_SW_Ver_Byte9 : 0|8@1+ (1,0) [0|255] ""  MBMU
 SG_ I2A_Byrack_Info2_SW_Ver_Byte10 : 8|8@1+ (1,0) [0|255] ""  MBMU
 SG_ I2A_Byrack_Info2_SW_Ver_Byte11 : 16|8@1+ (1,0) [0|255] ""  MBMU
 SG_ I2A_Byrack_Info2_SW_Ver_Byte12 : 24|8@1+ (1,0) [0|255] ""  MBMU
 SG_ I2A_Byrack_Info2_SW_Ver_Byte13 : 32|8@1+ (1,0) [0|255] ""  MBMU
 SG_ I2A_Byrack_Info2_SW_Ver_Byte14 : 40|8@1+ (1,0) [0|255] ""  MBMU
 SG_ I2A_Byrack_Info2_SW_Ver_Byte15 : 48|8@1+ (1,0) [0|255] ""  MBMU
 SG_ I2A_Byrack_Info2_SW_Ver_Byte16 : 56|8@1+ (1,0) [0|255] ""  MBMU

BO_ 2332156474 I2A_Byrack_info2__26: 8 IMM
 SG_ I2A_Byrack_Info2_SW_Ver_Byte9 : 0|8@1+ (1,0) [0|255] ""  MBMU
 SG_ I2A_Byrack_Info2_SW_Ver_Byte10 : 8|8@1+ (1,0) [0|255] ""  MBMU
 SG_ I2A_Byrack_Info2_SW_Ver_Byte11 : 16|8@1+ (1,0) [0|255] ""  MBMU
 SG_ I2A_Byrack_Info2_SW_Ver_Byte12 : 24|8@1+ (1,0) [0|255] ""  MBMU
 SG_ I2A_Byrack_Info2_SW_Ver_Byte13 : 32|8@1+ (1,0) [0|255] ""  MBMU
 SG_ I2A_Byrack_Info2_SW_Ver_Byte14 : 40|8@1+ (1,0) [0|255] ""  MBMU
 SG_ I2A_Byrack_Info2_SW_Ver_Byte15 : 48|8@1+ (1,0) [0|255] ""  MBMU
 SG_ I2A_Byrack_Info2_SW_Ver_Byte16 : 56|8@1+ (1,0) [0|255] ""  MBMU

BO_ 2332156475 I2A_Byrack_info2__27: 8 IMM
 SG_ I2A_Byrack_Info2_SW_Ver_Byte9 : 0|8@1+ (1,0) [0|255] ""  MBMU
 SG_ I2A_Byrack_Info2_SW_Ver_Byte10 : 8|8@1+ (1,0) [0|255] ""  MBMU
 SG_ I2A_Byrack_Info2_SW_Ver_Byte11 : 16|8@1+ (1,0) [0|255] ""  MBMU
 SG_ I2A_Byrack_Info2_SW_Ver_Byte12 : 24|8@1+ (1,0) [0|255] ""  MBMU
 SG_ I2A_Byrack_Info2_SW_Ver_Byte13 : 32|8@1+ (1,0) [0|255] ""  MBMU
 SG_ I2A_Byrack_Info2_SW_Ver_Byte14 : 40|8@1+ (1,0) [0|255] ""  MBMU
 SG_ I2A_Byrack_Info2_SW_Ver_Byte15 : 48|8@1+ (1,0) [0|255] ""  MBMU
 SG_ I2A_Byrack_Info2_SW_Ver_Byte16 : 56|8@1+ (1,0) [0|255] ""  MBMU

BO_ 2332156476 I2A_Byrack_info2__28: 8 IMM
 SG_ I2A_Byrack_Info2_SW_Ver_Byte9 : 0|8@1+ (1,0) [0|255] ""  MBMU
 SG_ I2A_Byrack_Info2_SW_Ver_Byte10 : 8|8@1+ (1,0) [0|255] ""  MBMU
 SG_ I2A_Byrack_Info2_SW_Ver_Byte11 : 16|8@1+ (1,0) [0|255] ""  MBMU
 SG_ I2A_Byrack_Info2_SW_Ver_Byte12 : 24|8@1+ (1,0) [0|255] ""  MBMU
 SG_ I2A_Byrack_Info2_SW_Ver_Byte13 : 32|8@1+ (1,0) [0|255] ""  MBMU
 SG_ I2A_Byrack_Info2_SW_Ver_Byte14 : 40|8@1+ (1,0) [0|255] ""  MBMU
 SG_ I2A_Byrack_Info2_SW_Ver_Byte15 : 48|8@1+ (1,0) [0|255] ""  MBMU
 SG_ I2A_Byrack_Info2_SW_Ver_Byte16 : 56|8@1+ (1,0) [0|255] ""  MBMU

BO_ 2332156477 I2A_Byrack_info2__29: 8 IMM
 SG_ I2A_Byrack_Info2_SW_Ver_Byte9 : 0|8@1+ (1,0) [0|255] ""  MBMU
 SG_ I2A_Byrack_Info2_SW_Ver_Byte10 : 8|8@1+ (1,0) [0|255] ""  MBMU
 SG_ I2A_Byrack_Info2_SW_Ver_Byte11 : 16|8@1+ (1,0) [0|255] ""  MBMU
 SG_ I2A_Byrack_Info2_SW_Ver_Byte12 : 24|8@1+ (1,0) [0|255] ""  MBMU
 SG_ I2A_Byrack_Info2_SW_Ver_Byte13 : 32|8@1+ (1,0) [0|255] ""  MBMU
 SG_ I2A_Byrack_Info2_SW_Ver_Byte14 : 40|8@1+ (1,0) [0|255] ""  MBMU
 SG_ I2A_Byrack_Info2_SW_Ver_Byte15 : 48|8@1+ (1,0) [0|255] ""  MBMU
 SG_ I2A_Byrack_Info2_SW_Ver_Byte16 : 56|8@1+ (1,0) [0|255] ""  MBMU

BO_ 2332156478 I2A_Byrack_info2__30: 8 IMM
 SG_ I2A_Byrack_Info2_SW_Ver_Byte9 : 0|8@1+ (1,0) [0|255] ""  MBMU
 SG_ I2A_Byrack_Info2_SW_Ver_Byte10 : 8|8@1+ (1,0) [0|255] ""  MBMU
 SG_ I2A_Byrack_Info2_SW_Ver_Byte11 : 16|8@1+ (1,0) [0|255] ""  MBMU
 SG_ I2A_Byrack_Info2_SW_Ver_Byte12 : 24|8@1+ (1,0) [0|255] ""  MBMU
 SG_ I2A_Byrack_Info2_SW_Ver_Byte13 : 32|8@1+ (1,0) [0|255] ""  MBMU
 SG_ I2A_Byrack_Info2_SW_Ver_Byte14 : 40|8@1+ (1,0) [0|255] ""  MBMU
 SG_ I2A_Byrack_Info2_SW_Ver_Byte15 : 48|8@1+ (1,0) [0|255] ""  MBMU
 SG_ I2A_Byrack_Info2_SW_Ver_Byte16 : 56|8@1+ (1,0) [0|255] ""  MBMU

BO_ 2332156479 I2A_Byrack_info2__31: 8 IMM
 SG_ I2A_Byrack_Info2_SW_Ver_Byte9 : 0|8@1+ (1,0) [0|255] ""  MBMU
 SG_ I2A_Byrack_Info2_SW_Ver_Byte10 : 8|8@1+ (1,0) [0|255] ""  MBMU
 SG_ I2A_Byrack_Info2_SW_Ver_Byte11 : 16|8@1+ (1,0) [0|255] ""  MBMU
 SG_ I2A_Byrack_Info2_SW_Ver_Byte12 : 24|8@1+ (1,0) [0|255] ""  MBMU
 SG_ I2A_Byrack_Info2_SW_Ver_Byte13 : 32|8@1+ (1,0) [0|255] ""  MBMU
 SG_ I2A_Byrack_Info2_SW_Ver_Byte14 : 40|8@1+ (1,0) [0|255] ""  MBMU
 SG_ I2A_Byrack_Info2_SW_Ver_Byte15 : 48|8@1+ (1,0) [0|255] ""  MBMU
 SG_ I2A_Byrack_Info2_SW_Ver_Byte16 : 56|8@1+ (1,0) [0|255] ""  MBMU

BO_ 2332156705 I2A_Byrack_info3__01: 8 IMM
 SG_ I2A_Byrack_Info3_HW_Ver_Byte1 : 0|8@1+ (1,0) [0|255] ""  MBMU
 SG_ I2A_Byrack_Info3_HW_Ver_Byte2 : 8|8@1+ (1,0) [0|255] ""  MBMU
 SG_ I2A_Byrack_Info3_HW_Ver_Byte3 : 16|8@1+ (1,0) [0|255] ""  MBMU
 SG_ I2A_Byrack_Info3_HW_Ver_Byte4 : 24|8@1+ (1,0) [0|255] ""  MBMU
 SG_ I2A_Byrack_Info3_HW_Ver_Byte5 : 32|8@1+ (1,0) [0|255] ""  MBMU
 SG_ I2A_Byrack_Info3_HW_Ver_Byte6 : 40|8@1+ (1,0) [0|255] ""  MBMU
 SG_ I2A_Byrack_Info3_HW_Ver_Byte7 : 48|8@1+ (1,0) [0|255] ""  MBMU
 SG_ I2A_Byrack_Info3_HW_Ver_Byte8 : 56|8@1+ (1,0) [0|255] ""  MBMU

BO_ 2332156706 I2A_Byrack_info3__02: 8 IMM
 SG_ I2A_Byrack_Info3_HW_Ver_Byte1 : 0|8@1+ (1,0) [0|255] ""  MBMU
 SG_ I2A_Byrack_Info3_HW_Ver_Byte2 : 8|8@1+ (1,0) [0|255] ""  MBMU
 SG_ I2A_Byrack_Info3_HW_Ver_Byte3 : 16|8@1+ (1,0) [0|255] ""  MBMU
 SG_ I2A_Byrack_Info3_HW_Ver_Byte4 : 24|8@1+ (1,0) [0|255] ""  MBMU
 SG_ I2A_Byrack_Info3_HW_Ver_Byte5 : 32|8@1+ (1,0) [0|255] ""  MBMU
 SG_ I2A_Byrack_Info3_HW_Ver_Byte6 : 40|8@1+ (1,0) [0|255] ""  MBMU
 SG_ I2A_Byrack_Info3_HW_Ver_Byte7 : 48|8@1+ (1,0) [0|255] ""  MBMU
 SG_ I2A_Byrack_Info3_HW_Ver_Byte8 : 56|8@1+ (1,0) [0|255] ""  MBMU

BO_ 2332156707 I2A_Byrack_info3__03: 8 IMM
 SG_ I2A_Byrack_Info3_HW_Ver_Byte1 : 0|8@1+ (1,0) [0|255] ""  MBMU
 SG_ I2A_Byrack_Info3_HW_Ver_Byte2 : 8|8@1+ (1,0) [0|255] ""  MBMU
 SG_ I2A_Byrack_Info3_HW_Ver_Byte3 : 16|8@1+ (1,0) [0|255] ""  MBMU
 SG_ I2A_Byrack_Info3_HW_Ver_Byte4 : 24|8@1+ (1,0) [0|255] ""  MBMU
 SG_ I2A_Byrack_Info3_HW_Ver_Byte5 : 32|8@1+ (1,0) [0|255] ""  MBMU
 SG_ I2A_Byrack_Info3_HW_Ver_Byte6 : 40|8@1+ (1,0) [0|255] ""  MBMU
 SG_ I2A_Byrack_Info3_HW_Ver_Byte7 : 48|8@1+ (1,0) [0|255] ""  MBMU
 SG_ I2A_Byrack_Info3_HW_Ver_Byte8 : 56|8@1+ (1,0) [0|255] ""  MBMU

BO_ 2332156708 I2A_Byrack_info3__04: 8 IMM
 SG_ I2A_Byrack_Info3_HW_Ver_Byte1 : 0|8@1+ (1,0) [0|255] ""  MBMU
 SG_ I2A_Byrack_Info3_HW_Ver_Byte2 : 8|8@1+ (1,0) [0|255] ""  MBMU
 SG_ I2A_Byrack_Info3_HW_Ver_Byte3 : 16|8@1+ (1,0) [0|255] ""  MBMU
 SG_ I2A_Byrack_Info3_HW_Ver_Byte4 : 24|8@1+ (1,0) [0|255] ""  MBMU
 SG_ I2A_Byrack_Info3_HW_Ver_Byte5 : 32|8@1+ (1,0) [0|255] ""  MBMU
 SG_ I2A_Byrack_Info3_HW_Ver_Byte6 : 40|8@1+ (1,0) [0|255] ""  MBMU
 SG_ I2A_Byrack_Info3_HW_Ver_Byte7 : 48|8@1+ (1,0) [0|255] ""  MBMU
 SG_ I2A_Byrack_Info3_HW_Ver_Byte8 : 56|8@1+ (1,0) [0|255] ""  MBMU

BO_ 2332156709 I2A_Byrack_info3__05: 8 IMM
 SG_ I2A_Byrack_Info3_HW_Ver_Byte1 : 0|8@1+ (1,0) [0|255] ""  MBMU
 SG_ I2A_Byrack_Info3_HW_Ver_Byte2 : 8|8@1+ (1,0) [0|255] ""  MBMU
 SG_ I2A_Byrack_Info3_HW_Ver_Byte3 : 16|8@1+ (1,0) [0|255] ""  MBMU
 SG_ I2A_Byrack_Info3_HW_Ver_Byte4 : 24|8@1+ (1,0) [0|255] ""  MBMU
 SG_ I2A_Byrack_Info3_HW_Ver_Byte5 : 32|8@1+ (1,0) [0|255] ""  MBMU
 SG_ I2A_Byrack_Info3_HW_Ver_Byte6 : 40|8@1+ (1,0) [0|255] ""  MBMU
 SG_ I2A_Byrack_Info3_HW_Ver_Byte7 : 48|8@1+ (1,0) [0|255] ""  MBMU
 SG_ I2A_Byrack_Info3_HW_Ver_Byte8 : 56|8@1+ (1,0) [0|255] ""  MBMU

BO_ 2332156710 I2A_Byrack_info3__06: 8 IMM
 SG_ I2A_Byrack_Info3_HW_Ver_Byte1 : 0|8@1+ (1,0) [0|255] ""  MBMU
 SG_ I2A_Byrack_Info3_HW_Ver_Byte2 : 8|8@1+ (1,0) [0|255] ""  MBMU
 SG_ I2A_Byrack_Info3_HW_Ver_Byte3 : 16|8@1+ (1,0) [0|255] ""  MBMU
 SG_ I2A_Byrack_Info3_HW_Ver_Byte4 : 24|8@1+ (1,0) [0|255] ""  MBMU
 SG_ I2A_Byrack_Info3_HW_Ver_Byte5 : 32|8@1+ (1,0) [0|255] ""  MBMU
 SG_ I2A_Byrack_Info3_HW_Ver_Byte6 : 40|8@1+ (1,0) [0|255] ""  MBMU
 SG_ I2A_Byrack_Info3_HW_Ver_Byte7 : 48|8@1+ (1,0) [0|255] ""  MBMU
 SG_ I2A_Byrack_Info3_HW_Ver_Byte8 : 56|8@1+ (1,0) [0|255] ""  MBMU

BO_ 2332156711 I2A_Byrack_info3__07: 8 IMM
 SG_ I2A_Byrack_Info3_HW_Ver_Byte1 : 0|8@1+ (1,0) [0|255] ""  MBMU
 SG_ I2A_Byrack_Info3_HW_Ver_Byte2 : 8|8@1+ (1,0) [0|255] ""  MBMU
 SG_ I2A_Byrack_Info3_HW_Ver_Byte3 : 16|8@1+ (1,0) [0|255] ""  MBMU
 SG_ I2A_Byrack_Info3_HW_Ver_Byte4 : 24|8@1+ (1,0) [0|255] ""  MBMU
 SG_ I2A_Byrack_Info3_HW_Ver_Byte5 : 32|8@1+ (1,0) [0|255] ""  MBMU
 SG_ I2A_Byrack_Info3_HW_Ver_Byte6 : 40|8@1+ (1,0) [0|255] ""  MBMU
 SG_ I2A_Byrack_Info3_HW_Ver_Byte7 : 48|8@1+ (1,0) [0|255] ""  MBMU
 SG_ I2A_Byrack_Info3_HW_Ver_Byte8 : 56|8@1+ (1,0) [0|255] ""  MBMU

BO_ 2332156712 I2A_Byrack_info3__08: 8 IMM
 SG_ I2A_Byrack_Info3_HW_Ver_Byte1 : 0|8@1+ (1,0) [0|255] ""  MBMU
 SG_ I2A_Byrack_Info3_HW_Ver_Byte2 : 8|8@1+ (1,0) [0|255] ""  MBMU
 SG_ I2A_Byrack_Info3_HW_Ver_Byte3 : 16|8@1+ (1,0) [0|255] ""  MBMU
 SG_ I2A_Byrack_Info3_HW_Ver_Byte4 : 24|8@1+ (1,0) [0|255] ""  MBMU
 SG_ I2A_Byrack_Info3_HW_Ver_Byte5 : 32|8@1+ (1,0) [0|255] ""  MBMU
 SG_ I2A_Byrack_Info3_HW_Ver_Byte6 : 40|8@1+ (1,0) [0|255] ""  MBMU
 SG_ I2A_Byrack_Info3_HW_Ver_Byte7 : 48|8@1+ (1,0) [0|255] ""  MBMU
 SG_ I2A_Byrack_Info3_HW_Ver_Byte8 : 56|8@1+ (1,0) [0|255] ""  MBMU

BO_ 2332156713 I2A_Byrack_info3__09: 8 IMM
 SG_ I2A_Byrack_Info3_HW_Ver_Byte1 : 0|8@1+ (1,0) [0|255] ""  MBMU
 SG_ I2A_Byrack_Info3_HW_Ver_Byte2 : 8|8@1+ (1,0) [0|255] ""  MBMU
 SG_ I2A_Byrack_Info3_HW_Ver_Byte3 : 16|8@1+ (1,0) [0|255] ""  MBMU
 SG_ I2A_Byrack_Info3_HW_Ver_Byte4 : 24|8@1+ (1,0) [0|255] ""  MBMU
 SG_ I2A_Byrack_Info3_HW_Ver_Byte5 : 32|8@1+ (1,0) [0|255] ""  MBMU
 SG_ I2A_Byrack_Info3_HW_Ver_Byte6 : 40|8@1+ (1,0) [0|255] ""  MBMU
 SG_ I2A_Byrack_Info3_HW_Ver_Byte7 : 48|8@1+ (1,0) [0|255] ""  MBMU
 SG_ I2A_Byrack_Info3_HW_Ver_Byte8 : 56|8@1+ (1,0) [0|255] ""  MBMU

BO_ 2332156714 I2A_Byrack_info3__10: 8 IMM
 SG_ I2A_Byrack_Info3_HW_Ver_Byte1 : 0|8@1+ (1,0) [0|255] ""  MBMU
 SG_ I2A_Byrack_Info3_HW_Ver_Byte2 : 8|8@1+ (1,0) [0|255] ""  MBMU
 SG_ I2A_Byrack_Info3_HW_Ver_Byte3 : 16|8@1+ (1,0) [0|255] ""  MBMU
 SG_ I2A_Byrack_Info3_HW_Ver_Byte4 : 24|8@1+ (1,0) [0|255] ""  MBMU
 SG_ I2A_Byrack_Info3_HW_Ver_Byte5 : 32|8@1+ (1,0) [0|255] ""  MBMU
 SG_ I2A_Byrack_Info3_HW_Ver_Byte6 : 40|8@1+ (1,0) [0|255] ""  MBMU
 SG_ I2A_Byrack_Info3_HW_Ver_Byte7 : 48|8@1+ (1,0) [0|255] ""  MBMU
 SG_ I2A_Byrack_Info3_HW_Ver_Byte8 : 56|8@1+ (1,0) [0|255] ""  MBMU

BO_ 2332156715 I2A_Byrack_info3__11: 8 IMM
 SG_ I2A_Byrack_Info3_HW_Ver_Byte1 : 0|8@1+ (1,0) [0|255] ""  MBMU
 SG_ I2A_Byrack_Info3_HW_Ver_Byte2 : 8|8@1+ (1,0) [0|255] ""  MBMU
 SG_ I2A_Byrack_Info3_HW_Ver_Byte3 : 16|8@1+ (1,0) [0|255] ""  MBMU
 SG_ I2A_Byrack_Info3_HW_Ver_Byte4 : 24|8@1+ (1,0) [0|255] ""  MBMU
 SG_ I2A_Byrack_Info3_HW_Ver_Byte5 : 32|8@1+ (1,0) [0|255] ""  MBMU
 SG_ I2A_Byrack_Info3_HW_Ver_Byte6 : 40|8@1+ (1,0) [0|255] ""  MBMU
 SG_ I2A_Byrack_Info3_HW_Ver_Byte7 : 48|8@1+ (1,0) [0|255] ""  MBMU
 SG_ I2A_Byrack_Info3_HW_Ver_Byte8 : 56|8@1+ (1,0) [0|255] ""  MBMU

BO_ 2332156716 I2A_Byrack_info3__12: 8 IMM
 SG_ I2A_Byrack_Info3_HW_Ver_Byte1 : 0|8@1+ (1,0) [0|255] ""  MBMU
 SG_ I2A_Byrack_Info3_HW_Ver_Byte2 : 8|8@1+ (1,0) [0|255] ""  MBMU
 SG_ I2A_Byrack_Info3_HW_Ver_Byte3 : 16|8@1+ (1,0) [0|255] ""  MBMU
 SG_ I2A_Byrack_Info3_HW_Ver_Byte4 : 24|8@1+ (1,0) [0|255] ""  MBMU
 SG_ I2A_Byrack_Info3_HW_Ver_Byte5 : 32|8@1+ (1,0) [0|255] ""  MBMU
 SG_ I2A_Byrack_Info3_HW_Ver_Byte6 : 40|8@1+ (1,0) [0|255] ""  MBMU
 SG_ I2A_Byrack_Info3_HW_Ver_Byte7 : 48|8@1+ (1,0) [0|255] ""  MBMU
 SG_ I2A_Byrack_Info3_HW_Ver_Byte8 : 56|8@1+ (1,0) [0|255] ""  MBMU

BO_ 2332156717 I2A_Byrack_info3__13: 8 IMM
 SG_ I2A_Byrack_Info3_HW_Ver_Byte1 : 0|8@1+ (1,0) [0|255] ""  MBMU
 SG_ I2A_Byrack_Info3_HW_Ver_Byte2 : 8|8@1+ (1,0) [0|255] ""  MBMU
 SG_ I2A_Byrack_Info3_HW_Ver_Byte3 : 16|8@1+ (1,0) [0|255] ""  MBMU
 SG_ I2A_Byrack_Info3_HW_Ver_Byte4 : 24|8@1+ (1,0) [0|255] ""  MBMU
 SG_ I2A_Byrack_Info3_HW_Ver_Byte5 : 32|8@1+ (1,0) [0|255] ""  MBMU
 SG_ I2A_Byrack_Info3_HW_Ver_Byte6 : 40|8@1+ (1,0) [0|255] ""  MBMU
 SG_ I2A_Byrack_Info3_HW_Ver_Byte7 : 48|8@1+ (1,0) [0|255] ""  MBMU
 SG_ I2A_Byrack_Info3_HW_Ver_Byte8 : 56|8@1+ (1,0) [0|255] ""  MBMU

BO_ 2332156718 I2A_Byrack_info3__14: 8 IMM
 SG_ I2A_Byrack_Info3_HW_Ver_Byte1 : 0|8@1+ (1,0) [0|255] ""  MBMU
 SG_ I2A_Byrack_Info3_HW_Ver_Byte2 : 8|8@1+ (1,0) [0|255] ""  MBMU
 SG_ I2A_Byrack_Info3_HW_Ver_Byte3 : 16|8@1+ (1,0) [0|255] ""  MBMU
 SG_ I2A_Byrack_Info3_HW_Ver_Byte4 : 24|8@1+ (1,0) [0|255] ""  MBMU
 SG_ I2A_Byrack_Info3_HW_Ver_Byte5 : 32|8@1+ (1,0) [0|255] ""  MBMU
 SG_ I2A_Byrack_Info3_HW_Ver_Byte6 : 40|8@1+ (1,0) [0|255] ""  MBMU
 SG_ I2A_Byrack_Info3_HW_Ver_Byte7 : 48|8@1+ (1,0) [0|255] ""  MBMU
 SG_ I2A_Byrack_Info3_HW_Ver_Byte8 : 56|8@1+ (1,0) [0|255] ""  MBMU

BO_ 2332156719 I2A_Byrack_info3__15: 8 IMM
 SG_ I2A_Byrack_Info3_HW_Ver_Byte1 : 0|8@1+ (1,0) [0|255] ""  MBMU
 SG_ I2A_Byrack_Info3_HW_Ver_Byte2 : 8|8@1+ (1,0) [0|255] ""  MBMU
 SG_ I2A_Byrack_Info3_HW_Ver_Byte3 : 16|8@1+ (1,0) [0|255] ""  MBMU
 SG_ I2A_Byrack_Info3_HW_Ver_Byte4 : 24|8@1+ (1,0) [0|255] ""  MBMU
 SG_ I2A_Byrack_Info3_HW_Ver_Byte5 : 32|8@1+ (1,0) [0|255] ""  MBMU
 SG_ I2A_Byrack_Info3_HW_Ver_Byte6 : 40|8@1+ (1,0) [0|255] ""  MBMU
 SG_ I2A_Byrack_Info3_HW_Ver_Byte7 : 48|8@1+ (1,0) [0|255] ""  MBMU
 SG_ I2A_Byrack_Info3_HW_Ver_Byte8 : 56|8@1+ (1,0) [0|255] ""  MBMU

BO_ 2332156720 I2A_Byrack_info3__16: 8 IMM
 SG_ I2A_Byrack_Info3_HW_Ver_Byte1 : 0|8@1+ (1,0) [0|255] ""  MBMU
 SG_ I2A_Byrack_Info3_HW_Ver_Byte2 : 8|8@1+ (1,0) [0|255] ""  MBMU
 SG_ I2A_Byrack_Info3_HW_Ver_Byte3 : 16|8@1+ (1,0) [0|255] ""  MBMU
 SG_ I2A_Byrack_Info3_HW_Ver_Byte4 : 24|8@1+ (1,0) [0|255] ""  MBMU
 SG_ I2A_Byrack_Info3_HW_Ver_Byte5 : 32|8@1+ (1,0) [0|255] ""  MBMU
 SG_ I2A_Byrack_Info3_HW_Ver_Byte6 : 40|8@1+ (1,0) [0|255] ""  MBMU
 SG_ I2A_Byrack_Info3_HW_Ver_Byte7 : 48|8@1+ (1,0) [0|255] ""  MBMU
 SG_ I2A_Byrack_Info3_HW_Ver_Byte8 : 56|8@1+ (1,0) [0|255] ""  MBMU

BO_ 2332156721 I2A_Byrack_info3__17: 8 IMM
 SG_ I2A_Byrack_Info3_HW_Ver_Byte1 : 0|8@1+ (1,0) [0|255] ""  MBMU
 SG_ I2A_Byrack_Info3_HW_Ver_Byte2 : 8|8@1+ (1,0) [0|255] ""  MBMU
 SG_ I2A_Byrack_Info3_HW_Ver_Byte3 : 16|8@1+ (1,0) [0|255] ""  MBMU
 SG_ I2A_Byrack_Info3_HW_Ver_Byte4 : 24|8@1+ (1,0) [0|255] ""  MBMU
 SG_ I2A_Byrack_Info3_HW_Ver_Byte5 : 32|8@1+ (1,0) [0|255] ""  MBMU
 SG_ I2A_Byrack_Info3_HW_Ver_Byte6 : 40|8@1+ (1,0) [0|255] ""  MBMU
 SG_ I2A_Byrack_Info3_HW_Ver_Byte7 : 48|8@1+ (1,0) [0|255] ""  MBMU
 SG_ I2A_Byrack_Info3_HW_Ver_Byte8 : 56|8@1+ (1,0) [0|255] ""  MBMU

BO_ 2332156722 I2A_Byrack_info3__18: 8 IMM
 SG_ I2A_Byrack_Info3_HW_Ver_Byte1 : 0|8@1+ (1,0) [0|255] ""  MBMU
 SG_ I2A_Byrack_Info3_HW_Ver_Byte2 : 8|8@1+ (1,0) [0|255] ""  MBMU
 SG_ I2A_Byrack_Info3_HW_Ver_Byte3 : 16|8@1+ (1,0) [0|255] ""  MBMU
 SG_ I2A_Byrack_Info3_HW_Ver_Byte4 : 24|8@1+ (1,0) [0|255] ""  MBMU
 SG_ I2A_Byrack_Info3_HW_Ver_Byte5 : 32|8@1+ (1,0) [0|255] ""  MBMU
 SG_ I2A_Byrack_Info3_HW_Ver_Byte6 : 40|8@1+ (1,0) [0|255] ""  MBMU
 SG_ I2A_Byrack_Info3_HW_Ver_Byte7 : 48|8@1+ (1,0) [0|255] ""  MBMU
 SG_ I2A_Byrack_Info3_HW_Ver_Byte8 : 56|8@1+ (1,0) [0|255] ""  MBMU

BO_ 2332156723 I2A_Byrack_info3__19: 8 IMM
 SG_ I2A_Byrack_Info3_HW_Ver_Byte1 : 0|8@1+ (1,0) [0|255] ""  MBMU
 SG_ I2A_Byrack_Info3_HW_Ver_Byte2 : 8|8@1+ (1,0) [0|255] ""  MBMU
 SG_ I2A_Byrack_Info3_HW_Ver_Byte3 : 16|8@1+ (1,0) [0|255] ""  MBMU
 SG_ I2A_Byrack_Info3_HW_Ver_Byte4 : 24|8@1+ (1,0) [0|255] ""  MBMU
 SG_ I2A_Byrack_Info3_HW_Ver_Byte5 : 32|8@1+ (1,0) [0|255] ""  MBMU
 SG_ I2A_Byrack_Info3_HW_Ver_Byte6 : 40|8@1+ (1,0) [0|255] ""  MBMU
 SG_ I2A_Byrack_Info3_HW_Ver_Byte7 : 48|8@1+ (1,0) [0|255] ""  MBMU
 SG_ I2A_Byrack_Info3_HW_Ver_Byte8 : 56|8@1+ (1,0) [0|255] ""  MBMU

BO_ 2332156724 I2A_Byrack_info3__20: 8 IMM
 SG_ I2A_Byrack_Info3_HW_Ver_Byte1 : 0|8@1+ (1,0) [0|255] ""  MBMU
 SG_ I2A_Byrack_Info3_HW_Ver_Byte2 : 8|8@1+ (1,0) [0|255] ""  MBMU
 SG_ I2A_Byrack_Info3_HW_Ver_Byte3 : 16|8@1+ (1,0) [0|255] ""  MBMU
 SG_ I2A_Byrack_Info3_HW_Ver_Byte4 : 24|8@1+ (1,0) [0|255] ""  MBMU
 SG_ I2A_Byrack_Info3_HW_Ver_Byte5 : 32|8@1+ (1,0) [0|255] ""  MBMU
 SG_ I2A_Byrack_Info3_HW_Ver_Byte6 : 40|8@1+ (1,0) [0|255] ""  MBMU
 SG_ I2A_Byrack_Info3_HW_Ver_Byte7 : 48|8@1+ (1,0) [0|255] ""  MBMU
 SG_ I2A_Byrack_Info3_HW_Ver_Byte8 : 56|8@1+ (1,0) [0|255] ""  MBMU

BO_ 2332156725 I2A_Byrack_info3__21: 8 IMM
 SG_ I2A_Byrack_Info3_HW_Ver_Byte1 : 0|8@1+ (1,0) [0|255] ""  MBMU
 SG_ I2A_Byrack_Info3_HW_Ver_Byte2 : 8|8@1+ (1,0) [0|255] ""  MBMU
 SG_ I2A_Byrack_Info3_HW_Ver_Byte3 : 16|8@1+ (1,0) [0|255] ""  MBMU
 SG_ I2A_Byrack_Info3_HW_Ver_Byte4 : 24|8@1+ (1,0) [0|255] ""  MBMU
 SG_ I2A_Byrack_Info3_HW_Ver_Byte5 : 32|8@1+ (1,0) [0|255] ""  MBMU
 SG_ I2A_Byrack_Info3_HW_Ver_Byte6 : 40|8@1+ (1,0) [0|255] ""  MBMU
 SG_ I2A_Byrack_Info3_HW_Ver_Byte7 : 48|8@1+ (1,0) [0|255] ""  MBMU
 SG_ I2A_Byrack_Info3_HW_Ver_Byte8 : 56|8@1+ (1,0) [0|255] ""  MBMU

BO_ 2332156726 I2A_Byrack_info3__22: 8 IMM
 SG_ I2A_Byrack_Info3_HW_Ver_Byte1 : 0|8@1+ (1,0) [0|255] ""  MBMU
 SG_ I2A_Byrack_Info3_HW_Ver_Byte2 : 8|8@1+ (1,0) [0|255] ""  MBMU
 SG_ I2A_Byrack_Info3_HW_Ver_Byte3 : 16|8@1+ (1,0) [0|255] ""  MBMU
 SG_ I2A_Byrack_Info3_HW_Ver_Byte4 : 24|8@1+ (1,0) [0|255] ""  MBMU
 SG_ I2A_Byrack_Info3_HW_Ver_Byte5 : 32|8@1+ (1,0) [0|255] ""  MBMU
 SG_ I2A_Byrack_Info3_HW_Ver_Byte6 : 40|8@1+ (1,0) [0|255] ""  MBMU
 SG_ I2A_Byrack_Info3_HW_Ver_Byte7 : 48|8@1+ (1,0) [0|255] ""  MBMU
 SG_ I2A_Byrack_Info3_HW_Ver_Byte8 : 56|8@1+ (1,0) [0|255] ""  MBMU

BO_ 2332156727 I2A_Byrack_info3__23: 8 IMM
 SG_ I2A_Byrack_Info3_HW_Ver_Byte1 : 0|8@1+ (1,0) [0|255] ""  MBMU
 SG_ I2A_Byrack_Info3_HW_Ver_Byte2 : 8|8@1+ (1,0) [0|255] ""  MBMU
 SG_ I2A_Byrack_Info3_HW_Ver_Byte3 : 16|8@1+ (1,0) [0|255] ""  MBMU
 SG_ I2A_Byrack_Info3_HW_Ver_Byte4 : 24|8@1+ (1,0) [0|255] ""  MBMU
 SG_ I2A_Byrack_Info3_HW_Ver_Byte5 : 32|8@1+ (1,0) [0|255] ""  MBMU
 SG_ I2A_Byrack_Info3_HW_Ver_Byte6 : 40|8@1+ (1,0) [0|255] ""  MBMU
 SG_ I2A_Byrack_Info3_HW_Ver_Byte7 : 48|8@1+ (1,0) [0|255] ""  MBMU
 SG_ I2A_Byrack_Info3_HW_Ver_Byte8 : 56|8@1+ (1,0) [0|255] ""  MBMU

BO_ 2332156728 I2A_Byrack_info3__24: 8 IMM
 SG_ I2A_Byrack_Info3_HW_Ver_Byte1 : 0|8@1+ (1,0) [0|255] ""  MBMU
 SG_ I2A_Byrack_Info3_HW_Ver_Byte2 : 8|8@1+ (1,0) [0|255] ""  MBMU
 SG_ I2A_Byrack_Info3_HW_Ver_Byte3 : 16|8@1+ (1,0) [0|255] ""  MBMU
 SG_ I2A_Byrack_Info3_HW_Ver_Byte4 : 24|8@1+ (1,0) [0|255] ""  MBMU
 SG_ I2A_Byrack_Info3_HW_Ver_Byte5 : 32|8@1+ (1,0) [0|255] ""  MBMU
 SG_ I2A_Byrack_Info3_HW_Ver_Byte6 : 40|8@1+ (1,0) [0|255] ""  MBMU
 SG_ I2A_Byrack_Info3_HW_Ver_Byte7 : 48|8@1+ (1,0) [0|255] ""  MBMU
 SG_ I2A_Byrack_Info3_HW_Ver_Byte8 : 56|8@1+ (1,0) [0|255] ""  MBMU

BO_ 2332156729 I2A_Byrack_info3__25: 8 IMM
 SG_ I2A_Byrack_Info3_HW_Ver_Byte1 : 0|8@1+ (1,0) [0|255] ""  MBMU
 SG_ I2A_Byrack_Info3_HW_Ver_Byte2 : 8|8@1+ (1,0) [0|255] ""  MBMU
 SG_ I2A_Byrack_Info3_HW_Ver_Byte3 : 16|8@1+ (1,0) [0|255] ""  MBMU
 SG_ I2A_Byrack_Info3_HW_Ver_Byte4 : 24|8@1+ (1,0) [0|255] ""  MBMU
 SG_ I2A_Byrack_Info3_HW_Ver_Byte5 : 32|8@1+ (1,0) [0|255] ""  MBMU
 SG_ I2A_Byrack_Info3_HW_Ver_Byte6 : 40|8@1+ (1,0) [0|255] ""  MBMU
 SG_ I2A_Byrack_Info3_HW_Ver_Byte7 : 48|8@1+ (1,0) [0|255] ""  MBMU
 SG_ I2A_Byrack_Info3_HW_Ver_Byte8 : 56|8@1+ (1,0) [0|255] ""  MBMU

BO_ 2332156730 I2A_Byrack_info3__26: 8 IMM
 SG_ I2A_Byrack_Info3_HW_Ver_Byte1 : 0|8@1+ (1,0) [0|255] ""  MBMU
 SG_ I2A_Byrack_Info3_HW_Ver_Byte2 : 8|8@1+ (1,0) [0|255] ""  MBMU
 SG_ I2A_Byrack_Info3_HW_Ver_Byte3 : 16|8@1+ (1,0) [0|255] ""  MBMU
 SG_ I2A_Byrack_Info3_HW_Ver_Byte4 : 24|8@1+ (1,0) [0|255] ""  MBMU
 SG_ I2A_Byrack_Info3_HW_Ver_Byte5 : 32|8@1+ (1,0) [0|255] ""  MBMU
 SG_ I2A_Byrack_Info3_HW_Ver_Byte6 : 40|8@1+ (1,0) [0|255] ""  MBMU
 SG_ I2A_Byrack_Info3_HW_Ver_Byte7 : 48|8@1+ (1,0) [0|255] ""  MBMU
 SG_ I2A_Byrack_Info3_HW_Ver_Byte8 : 56|8@1+ (1,0) [0|255] ""  MBMU

BO_ 2332156731 I2A_Byrack_info3__27: 8 IMM
 SG_ I2A_Byrack_Info3_HW_Ver_Byte1 : 0|8@1+ (1,0) [0|255] ""  MBMU
 SG_ I2A_Byrack_Info3_HW_Ver_Byte2 : 8|8@1+ (1,0) [0|255] ""  MBMU
 SG_ I2A_Byrack_Info3_HW_Ver_Byte3 : 16|8@1+ (1,0) [0|255] ""  MBMU
 SG_ I2A_Byrack_Info3_HW_Ver_Byte4 : 24|8@1+ (1,0) [0|255] ""  MBMU
 SG_ I2A_Byrack_Info3_HW_Ver_Byte5 : 32|8@1+ (1,0) [0|255] ""  MBMU
 SG_ I2A_Byrack_Info3_HW_Ver_Byte6 : 40|8@1+ (1,0) [0|255] ""  MBMU
 SG_ I2A_Byrack_Info3_HW_Ver_Byte7 : 48|8@1+ (1,0) [0|255] ""  MBMU
 SG_ I2A_Byrack_Info3_HW_Ver_Byte8 : 56|8@1+ (1,0) [0|255] ""  MBMU

BO_ 2332156732 I2A_Byrack_info3__28: 8 IMM
 SG_ I2A_Byrack_Info3_HW_Ver_Byte1 : 0|8@1+ (1,0) [0|255] ""  MBMU
 SG_ I2A_Byrack_Info3_HW_Ver_Byte2 : 8|8@1+ (1,0) [0|255] ""  MBMU
 SG_ I2A_Byrack_Info3_HW_Ver_Byte3 : 16|8@1+ (1,0) [0|255] ""  MBMU
 SG_ I2A_Byrack_Info3_HW_Ver_Byte4 : 24|8@1+ (1,0) [0|255] ""  MBMU
 SG_ I2A_Byrack_Info3_HW_Ver_Byte5 : 32|8@1+ (1,0) [0|255] ""  MBMU
 SG_ I2A_Byrack_Info3_HW_Ver_Byte6 : 40|8@1+ (1,0) [0|255] ""  MBMU
 SG_ I2A_Byrack_Info3_HW_Ver_Byte7 : 48|8@1+ (1,0) [0|255] ""  MBMU
 SG_ I2A_Byrack_Info3_HW_Ver_Byte8 : 56|8@1+ (1,0) [0|255] ""  MBMU

BO_ 2332156733 I2A_Byrack_info3__29: 8 IMM
 SG_ I2A_Byrack_Info3_HW_Ver_Byte1 : 0|8@1+ (1,0) [0|255] ""  MBMU
 SG_ I2A_Byrack_Info3_HW_Ver_Byte2 : 8|8@1+ (1,0) [0|255] ""  MBMU
 SG_ I2A_Byrack_Info3_HW_Ver_Byte3 : 16|8@1+ (1,0) [0|255] ""  MBMU
 SG_ I2A_Byrack_Info3_HW_Ver_Byte4 : 24|8@1+ (1,0) [0|255] ""  MBMU
 SG_ I2A_Byrack_Info3_HW_Ver_Byte5 : 32|8@1+ (1,0) [0|255] ""  MBMU
 SG_ I2A_Byrack_Info3_HW_Ver_Byte6 : 40|8@1+ (1,0) [0|255] ""  MBMU
 SG_ I2A_Byrack_Info3_HW_Ver_Byte7 : 48|8@1+ (1,0) [0|255] ""  MBMU
 SG_ I2A_Byrack_Info3_HW_Ver_Byte8 : 56|8@1+ (1,0) [0|255] ""  MBMU

BO_ 2332156734 I2A_Byrack_info3__30: 8 IMM
 SG_ I2A_Byrack_Info3_HW_Ver_Byte1 : 0|8@1+ (1,0) [0|255] ""  MBMU
 SG_ I2A_Byrack_Info3_HW_Ver_Byte2 : 8|8@1+ (1,0) [0|255] ""  MBMU
 SG_ I2A_Byrack_Info3_HW_Ver_Byte3 : 16|8@1+ (1,0) [0|255] ""  MBMU
 SG_ I2A_Byrack_Info3_HW_Ver_Byte4 : 24|8@1+ (1,0) [0|255] ""  MBMU
 SG_ I2A_Byrack_Info3_HW_Ver_Byte5 : 32|8@1+ (1,0) [0|255] ""  MBMU
 SG_ I2A_Byrack_Info3_HW_Ver_Byte6 : 40|8@1+ (1,0) [0|255] ""  MBMU
 SG_ I2A_Byrack_Info3_HW_Ver_Byte7 : 48|8@1+ (1,0) [0|255] ""  MBMU
 SG_ I2A_Byrack_Info3_HW_Ver_Byte8 : 56|8@1+ (1,0) [0|255] ""  MBMU

BO_ 2332156735 I2A_Byrack_info3__31: 8 IMM
 SG_ I2A_Byrack_Info3_HW_Ver_Byte1 : 0|8@1+ (1,0) [0|255] ""  MBMU
 SG_ I2A_Byrack_Info3_HW_Ver_Byte2 : 8|8@1+ (1,0) [0|255] ""  MBMU
 SG_ I2A_Byrack_Info3_HW_Ver_Byte3 : 16|8@1+ (1,0) [0|255] ""  MBMU
 SG_ I2A_Byrack_Info3_HW_Ver_Byte4 : 24|8@1+ (1,0) [0|255] ""  MBMU
 SG_ I2A_Byrack_Info3_HW_Ver_Byte5 : 32|8@1+ (1,0) [0|255] ""  MBMU
 SG_ I2A_Byrack_Info3_HW_Ver_Byte6 : 40|8@1+ (1,0) [0|255] ""  MBMU
 SG_ I2A_Byrack_Info3_HW_Ver_Byte7 : 48|8@1+ (1,0) [0|255] ""  MBMU
 SG_ I2A_Byrack_Info3_HW_Ver_Byte8 : 56|8@1+ (1,0) [0|255] ""  MBMU

BO_ 2332156961 I2A_Byrack_info4__01: 8 IMM
 SG_ I2A_Byrack_Info4_HW_Ver_Byte9 : 0|8@1+ (1,0) [0|255] ""  MBMU
 SG_ I2A_Byrack_Info4_HW_Ver_Byte10 : 8|8@1+ (1,0) [0|255] ""  MBMU
 SG_ I2A_Byrack_Info4_HW_Ver_Byte11 : 16|8@1+ (1,0) [0|255] ""  MBMU
 SG_ I2A_Byrack_Info4_HW_Ver_Byte12 : 24|8@1+ (1,0) [0|255] ""  MBMU
 SG_ I2A_Byrack_Info4_HW_Ver_Byte13 : 32|8@1+ (1,0) [0|255] ""  MBMU
 SG_ I2A_Byrack_Info4_HW_Ver_Byte14 : 40|8@1+ (1,0) [0|255] ""  MBMU
 SG_ I2A_Byrack_Info4_HW_Ver_Byte15 : 48|8@1+ (1,0) [0|255] ""  MBMU
 SG_ I2A_Byrack_Info4_HW_Ver_Byte16 : 56|8@1+ (1,0) [0|255] ""  MBMU

BO_ 2332156962 I2A_Byrack_info4__02: 8 IMM
 SG_ I2A_Byrack_Info4_HW_Ver_Byte9 : 0|8@1+ (1,0) [0|255] ""  MBMU
 SG_ I2A_Byrack_Info4_HW_Ver_Byte10 : 8|8@1+ (1,0) [0|255] ""  MBMU
 SG_ I2A_Byrack_Info4_HW_Ver_Byte11 : 16|8@1+ (1,0) [0|255] ""  MBMU
 SG_ I2A_Byrack_Info4_HW_Ver_Byte12 : 24|8@1+ (1,0) [0|255] ""  MBMU
 SG_ I2A_Byrack_Info4_HW_Ver_Byte13 : 32|8@1+ (1,0) [0|255] ""  MBMU
 SG_ I2A_Byrack_Info4_HW_Ver_Byte14 : 40|8@1+ (1,0) [0|255] ""  MBMU
 SG_ I2A_Byrack_Info4_HW_Ver_Byte15 : 48|8@1+ (1,0) [0|255] ""  MBMU
 SG_ I2A_Byrack_Info4_HW_Ver_Byte16 : 56|8@1+ (1,0) [0|255] ""  MBMU

BO_ 2332156963 I2A_Byrack_info4__03: 8 IMM
 SG_ I2A_Byrack_Info4_HW_Ver_Byte9 : 0|8@1+ (1,0) [0|255] ""  MBMU
 SG_ I2A_Byrack_Info4_HW_Ver_Byte10 : 8|8@1+ (1,0) [0|255] ""  MBMU
 SG_ I2A_Byrack_Info4_HW_Ver_Byte11 : 16|8@1+ (1,0) [0|255] ""  MBMU
 SG_ I2A_Byrack_Info4_HW_Ver_Byte12 : 24|8@1+ (1,0) [0|255] ""  MBMU
 SG_ I2A_Byrack_Info4_HW_Ver_Byte13 : 32|8@1+ (1,0) [0|255] ""  MBMU
 SG_ I2A_Byrack_Info4_HW_Ver_Byte14 : 40|8@1+ (1,0) [0|255] ""  MBMU
 SG_ I2A_Byrack_Info4_HW_Ver_Byte15 : 48|8@1+ (1,0) [0|255] ""  MBMU
 SG_ I2A_Byrack_Info4_HW_Ver_Byte16 : 56|8@1+ (1,0) [0|255] ""  MBMU

BO_ 2332156964 I2A_Byrack_info4__04: 8 IMM
 SG_ I2A_Byrack_Info4_HW_Ver_Byte9 : 0|8@1+ (1,0) [0|255] ""  MBMU
 SG_ I2A_Byrack_Info4_HW_Ver_Byte10 : 8|8@1+ (1,0) [0|255] ""  MBMU
 SG_ I2A_Byrack_Info4_HW_Ver_Byte11 : 16|8@1+ (1,0) [0|255] ""  MBMU
 SG_ I2A_Byrack_Info4_HW_Ver_Byte12 : 24|8@1+ (1,0) [0|255] ""  MBMU
 SG_ I2A_Byrack_Info4_HW_Ver_Byte13 : 32|8@1+ (1,0) [0|255] ""  MBMU
 SG_ I2A_Byrack_Info4_HW_Ver_Byte14 : 40|8@1+ (1,0) [0|255] ""  MBMU
 SG_ I2A_Byrack_Info4_HW_Ver_Byte15 : 48|8@1+ (1,0) [0|255] ""  MBMU
 SG_ I2A_Byrack_Info4_HW_Ver_Byte16 : 56|8@1+ (1,0) [0|255] ""  MBMU

BO_ 2332156965 I2A_Byrack_info4__05: 8 IMM
 SG_ I2A_Byrack_Info4_HW_Ver_Byte9 : 0|8@1+ (1,0) [0|255] ""  MBMU
 SG_ I2A_Byrack_Info4_HW_Ver_Byte10 : 8|8@1+ (1,0) [0|255] ""  MBMU
 SG_ I2A_Byrack_Info4_HW_Ver_Byte11 : 16|8@1+ (1,0) [0|255] ""  MBMU
 SG_ I2A_Byrack_Info4_HW_Ver_Byte12 : 24|8@1+ (1,0) [0|255] ""  MBMU
 SG_ I2A_Byrack_Info4_HW_Ver_Byte13 : 32|8@1+ (1,0) [0|255] ""  MBMU
 SG_ I2A_Byrack_Info4_HW_Ver_Byte14 : 40|8@1+ (1,0) [0|255] ""  MBMU
 SG_ I2A_Byrack_Info4_HW_Ver_Byte15 : 48|8@1+ (1,0) [0|255] ""  MBMU
 SG_ I2A_Byrack_Info4_HW_Ver_Byte16 : 56|8@1+ (1,0) [0|255] ""  MBMU

BO_ 2332156966 I2A_Byrack_info4__06: 8 IMM
 SG_ I2A_Byrack_Info4_HW_Ver_Byte9 : 0|8@1+ (1,0) [0|255] ""  MBMU
 SG_ I2A_Byrack_Info4_HW_Ver_Byte10 : 8|8@1+ (1,0) [0|255] ""  MBMU
 SG_ I2A_Byrack_Info4_HW_Ver_Byte11 : 16|8@1+ (1,0) [0|255] ""  MBMU
 SG_ I2A_Byrack_Info4_HW_Ver_Byte12 : 24|8@1+ (1,0) [0|255] ""  MBMU
 SG_ I2A_Byrack_Info4_HW_Ver_Byte13 : 32|8@1+ (1,0) [0|255] ""  MBMU
 SG_ I2A_Byrack_Info4_HW_Ver_Byte14 : 40|8@1+ (1,0) [0|255] ""  MBMU
 SG_ I2A_Byrack_Info4_HW_Ver_Byte15 : 48|8@1+ (1,0) [0|255] ""  MBMU
 SG_ I2A_Byrack_Info4_HW_Ver_Byte16 : 56|8@1+ (1,0) [0|255] ""  MBMU

BO_ 2332156967 I2A_Byrack_info4__07: 8 IMM
 SG_ I2A_Byrack_Info4_HW_Ver_Byte9 : 0|8@1+ (1,0) [0|255] ""  MBMU
 SG_ I2A_Byrack_Info4_HW_Ver_Byte10 : 8|8@1+ (1,0) [0|255] ""  MBMU
 SG_ I2A_Byrack_Info4_HW_Ver_Byte11 : 16|8@1+ (1,0) [0|255] ""  MBMU
 SG_ I2A_Byrack_Info4_HW_Ver_Byte12 : 24|8@1+ (1,0) [0|255] ""  MBMU
 SG_ I2A_Byrack_Info4_HW_Ver_Byte13 : 32|8@1+ (1,0) [0|255] ""  MBMU
 SG_ I2A_Byrack_Info4_HW_Ver_Byte14 : 40|8@1+ (1,0) [0|255] ""  MBMU
 SG_ I2A_Byrack_Info4_HW_Ver_Byte15 : 48|8@1+ (1,0) [0|255] ""  MBMU
 SG_ I2A_Byrack_Info4_HW_Ver_Byte16 : 56|8@1+ (1,0) [0|255] ""  MBMU

BO_ 2332156968 I2A_Byrack_info4__08: 8 IMM
 SG_ I2A_Byrack_Info4_HW_Ver_Byte9 : 0|8@1+ (1,0) [0|255] ""  MBMU
 SG_ I2A_Byrack_Info4_HW_Ver_Byte10 : 8|8@1+ (1,0) [0|255] ""  MBMU
 SG_ I2A_Byrack_Info4_HW_Ver_Byte11 : 16|8@1+ (1,0) [0|255] ""  MBMU
 SG_ I2A_Byrack_Info4_HW_Ver_Byte12 : 24|8@1+ (1,0) [0|255] ""  MBMU
 SG_ I2A_Byrack_Info4_HW_Ver_Byte13 : 32|8@1+ (1,0) [0|255] ""  MBMU
 SG_ I2A_Byrack_Info4_HW_Ver_Byte14 : 40|8@1+ (1,0) [0|255] ""  MBMU
 SG_ I2A_Byrack_Info4_HW_Ver_Byte15 : 48|8@1+ (1,0) [0|255] ""  MBMU
 SG_ I2A_Byrack_Info4_HW_Ver_Byte16 : 56|8@1+ (1,0) [0|255] ""  MBMU

BO_ 2332156969 I2A_Byrack_info4__09: 8 IMM
 SG_ I2A_Byrack_Info4_HW_Ver_Byte9 : 0|8@1+ (1,0) [0|255] ""  MBMU
 SG_ I2A_Byrack_Info4_HW_Ver_Byte10 : 8|8@1+ (1,0) [0|255] ""  MBMU
 SG_ I2A_Byrack_Info4_HW_Ver_Byte11 : 16|8@1+ (1,0) [0|255] ""  MBMU
 SG_ I2A_Byrack_Info4_HW_Ver_Byte12 : 24|8@1+ (1,0) [0|255] ""  MBMU
 SG_ I2A_Byrack_Info4_HW_Ver_Byte13 : 32|8@1+ (1,0) [0|255] ""  MBMU
 SG_ I2A_Byrack_Info4_HW_Ver_Byte14 : 40|8@1+ (1,0) [0|255] ""  MBMU
 SG_ I2A_Byrack_Info4_HW_Ver_Byte15 : 48|8@1+ (1,0) [0|255] ""  MBMU
 SG_ I2A_Byrack_Info4_HW_Ver_Byte16 : 56|8@1+ (1,0) [0|255] ""  MBMU

BO_ 2332156970 I2A_Byrack_info4__10: 8 IMM
 SG_ I2A_Byrack_Info4_HW_Ver_Byte9 : 0|8@1+ (1,0) [0|255] ""  MBMU
 SG_ I2A_Byrack_Info4_HW_Ver_Byte10 : 8|8@1+ (1,0) [0|255] ""  MBMU
 SG_ I2A_Byrack_Info4_HW_Ver_Byte11 : 16|8@1+ (1,0) [0|255] ""  MBMU
 SG_ I2A_Byrack_Info4_HW_Ver_Byte12 : 24|8@1+ (1,0) [0|255] ""  MBMU
 SG_ I2A_Byrack_Info4_HW_Ver_Byte13 : 32|8@1+ (1,0) [0|255] ""  MBMU
 SG_ I2A_Byrack_Info4_HW_Ver_Byte14 : 40|8@1+ (1,0) [0|255] ""  MBMU
 SG_ I2A_Byrack_Info4_HW_Ver_Byte15 : 48|8@1+ (1,0) [0|255] ""  MBMU
 SG_ I2A_Byrack_Info4_HW_Ver_Byte16 : 56|8@1+ (1,0) [0|255] ""  MBMU

BO_ 2332156971 I2A_Byrack_info4__11: 8 IMM
 SG_ I2A_Byrack_Info4_HW_Ver_Byte9 : 0|8@1+ (1,0) [0|255] ""  MBMU
 SG_ I2A_Byrack_Info4_HW_Ver_Byte10 : 8|8@1+ (1,0) [0|255] ""  MBMU
 SG_ I2A_Byrack_Info4_HW_Ver_Byte11 : 16|8@1+ (1,0) [0|255] ""  MBMU
 SG_ I2A_Byrack_Info4_HW_Ver_Byte12 : 24|8@1+ (1,0) [0|255] ""  MBMU
 SG_ I2A_Byrack_Info4_HW_Ver_Byte13 : 32|8@1+ (1,0) [0|255] ""  MBMU
 SG_ I2A_Byrack_Info4_HW_Ver_Byte14 : 40|8@1+ (1,0) [0|255] ""  MBMU
 SG_ I2A_Byrack_Info4_HW_Ver_Byte15 : 48|8@1+ (1,0) [0|255] ""  MBMU
 SG_ I2A_Byrack_Info4_HW_Ver_Byte16 : 56|8@1+ (1,0) [0|255] ""  MBMU

BO_ 2332156972 I2A_Byrack_info4__12: 8 IMM
 SG_ I2A_Byrack_Info4_HW_Ver_Byte9 : 0|8@1+ (1,0) [0|255] ""  MBMU
 SG_ I2A_Byrack_Info4_HW_Ver_Byte10 : 8|8@1+ (1,0) [0|255] ""  MBMU
 SG_ I2A_Byrack_Info4_HW_Ver_Byte11 : 16|8@1+ (1,0) [0|255] ""  MBMU
 SG_ I2A_Byrack_Info4_HW_Ver_Byte12 : 24|8@1+ (1,0) [0|255] ""  MBMU
 SG_ I2A_Byrack_Info4_HW_Ver_Byte13 : 32|8@1+ (1,0) [0|255] ""  MBMU
 SG_ I2A_Byrack_Info4_HW_Ver_Byte14 : 40|8@1+ (1,0) [0|255] ""  MBMU
 SG_ I2A_Byrack_Info4_HW_Ver_Byte15 : 48|8@1+ (1,0) [0|255] ""  MBMU
 SG_ I2A_Byrack_Info4_HW_Ver_Byte16 : 56|8@1+ (1,0) [0|255] ""  MBMU

BO_ 2332156973 I2A_Byrack_info4__13: 8 IMM
 SG_ I2A_Byrack_Info4_HW_Ver_Byte9 : 0|8@1+ (1,0) [0|255] ""  MBMU
 SG_ I2A_Byrack_Info4_HW_Ver_Byte10 : 8|8@1+ (1,0) [0|255] ""  MBMU
 SG_ I2A_Byrack_Info4_HW_Ver_Byte11 : 16|8@1+ (1,0) [0|255] ""  MBMU
 SG_ I2A_Byrack_Info4_HW_Ver_Byte12 : 24|8@1+ (1,0) [0|255] ""  MBMU
 SG_ I2A_Byrack_Info4_HW_Ver_Byte13 : 32|8@1+ (1,0) [0|255] ""  MBMU
 SG_ I2A_Byrack_Info4_HW_Ver_Byte14 : 40|8@1+ (1,0) [0|255] ""  MBMU
 SG_ I2A_Byrack_Info4_HW_Ver_Byte15 : 48|8@1+ (1,0) [0|255] ""  MBMU
 SG_ I2A_Byrack_Info4_HW_Ver_Byte16 : 56|8@1+ (1,0) [0|255] ""  MBMU

BO_ 2332156974 I2A_Byrack_info4__14: 8 IMM
 SG_ I2A_Byrack_Info4_HW_Ver_Byte9 : 0|8@1+ (1,0) [0|255] ""  MBMU
 SG_ I2A_Byrack_Info4_HW_Ver_Byte10 : 8|8@1+ (1,0) [0|255] ""  MBMU
 SG_ I2A_Byrack_Info4_HW_Ver_Byte11 : 16|8@1+ (1,0) [0|255] ""  MBMU
 SG_ I2A_Byrack_Info4_HW_Ver_Byte12 : 24|8@1+ (1,0) [0|255] ""  MBMU
 SG_ I2A_Byrack_Info4_HW_Ver_Byte13 : 32|8@1+ (1,0) [0|255] ""  MBMU
 SG_ I2A_Byrack_Info4_HW_Ver_Byte14 : 40|8@1+ (1,0) [0|255] ""  MBMU
 SG_ I2A_Byrack_Info4_HW_Ver_Byte15 : 48|8@1+ (1,0) [0|255] ""  MBMU
 SG_ I2A_Byrack_Info4_HW_Ver_Byte16 : 56|8@1+ (1,0) [0|255] ""  MBMU

BO_ 2332156975 I2A_Byrack_info4__15: 8 IMM
 SG_ I2A_Byrack_Info4_HW_Ver_Byte9 : 0|8@1+ (1,0) [0|255] ""  MBMU
 SG_ I2A_Byrack_Info4_HW_Ver_Byte10 : 8|8@1+ (1,0) [0|255] ""  MBMU
 SG_ I2A_Byrack_Info4_HW_Ver_Byte11 : 16|8@1+ (1,0) [0|255] ""  MBMU
 SG_ I2A_Byrack_Info4_HW_Ver_Byte12 : 24|8@1+ (1,0) [0|255] ""  MBMU
 SG_ I2A_Byrack_Info4_HW_Ver_Byte13 : 32|8@1+ (1,0) [0|255] ""  MBMU
 SG_ I2A_Byrack_Info4_HW_Ver_Byte14 : 40|8@1+ (1,0) [0|255] ""  MBMU
 SG_ I2A_Byrack_Info4_HW_Ver_Byte15 : 48|8@1+ (1,0) [0|255] ""  MBMU
 SG_ I2A_Byrack_Info4_HW_Ver_Byte16 : 56|8@1+ (1,0) [0|255] ""  MBMU

BO_ 2332156976 I2A_Byrack_info4__16: 8 IMM
 SG_ I2A_Byrack_Info4_HW_Ver_Byte9 : 0|8@1+ (1,0) [0|255] ""  MBMU
 SG_ I2A_Byrack_Info4_HW_Ver_Byte10 : 8|8@1+ (1,0) [0|255] ""  MBMU
 SG_ I2A_Byrack_Info4_HW_Ver_Byte11 : 16|8@1+ (1,0) [0|255] ""  MBMU
 SG_ I2A_Byrack_Info4_HW_Ver_Byte12 : 24|8@1+ (1,0) [0|255] ""  MBMU
 SG_ I2A_Byrack_Info4_HW_Ver_Byte13 : 32|8@1+ (1,0) [0|255] ""  MBMU
 SG_ I2A_Byrack_Info4_HW_Ver_Byte14 : 40|8@1+ (1,0) [0|255] ""  MBMU
 SG_ I2A_Byrack_Info4_HW_Ver_Byte15 : 48|8@1+ (1,0) [0|255] ""  MBMU
 SG_ I2A_Byrack_Info4_HW_Ver_Byte16 : 56|8@1+ (1,0) [0|255] ""  MBMU

BO_ 2332156977 I2A_Byrack_info4__17: 8 IMM
 SG_ I2A_Byrack_Info4_HW_Ver_Byte9 : 0|8@1+ (1,0) [0|255] ""  MBMU
 SG_ I2A_Byrack_Info4_HW_Ver_Byte10 : 8|8@1+ (1,0) [0|255] ""  MBMU
 SG_ I2A_Byrack_Info4_HW_Ver_Byte11 : 16|8@1+ (1,0) [0|255] ""  MBMU
 SG_ I2A_Byrack_Info4_HW_Ver_Byte12 : 24|8@1+ (1,0) [0|255] ""  MBMU
 SG_ I2A_Byrack_Info4_HW_Ver_Byte13 : 32|8@1+ (1,0) [0|255] ""  MBMU
 SG_ I2A_Byrack_Info4_HW_Ver_Byte14 : 40|8@1+ (1,0) [0|255] ""  MBMU
 SG_ I2A_Byrack_Info4_HW_Ver_Byte15 : 48|8@1+ (1,0) [0|255] ""  MBMU
 SG_ I2A_Byrack_Info4_HW_Ver_Byte16 : 56|8@1+ (1,0) [0|255] ""  MBMU

BO_ 2332156978 I2A_Byrack_info4__18: 8 IMM
 SG_ I2A_Byrack_Info4_HW_Ver_Byte9 : 0|8@1+ (1,0) [0|255] ""  MBMU
 SG_ I2A_Byrack_Info4_HW_Ver_Byte10 : 8|8@1+ (1,0) [0|255] ""  MBMU
 SG_ I2A_Byrack_Info4_HW_Ver_Byte11 : 16|8@1+ (1,0) [0|255] ""  MBMU
 SG_ I2A_Byrack_Info4_HW_Ver_Byte12 : 24|8@1+ (1,0) [0|255] ""  MBMU
 SG_ I2A_Byrack_Info4_HW_Ver_Byte13 : 32|8@1+ (1,0) [0|255] ""  MBMU
 SG_ I2A_Byrack_Info4_HW_Ver_Byte14 : 40|8@1+ (1,0) [0|255] ""  MBMU
 SG_ I2A_Byrack_Info4_HW_Ver_Byte15 : 48|8@1+ (1,0) [0|255] ""  MBMU
 SG_ I2A_Byrack_Info4_HW_Ver_Byte16 : 56|8@1+ (1,0) [0|255] ""  MBMU

BO_ 2332156979 I2A_Byrack_info4__19: 8 IMM
 SG_ I2A_Byrack_Info4_HW_Ver_Byte9 : 0|8@1+ (1,0) [0|255] ""  MBMU
 SG_ I2A_Byrack_Info4_HW_Ver_Byte10 : 8|8@1+ (1,0) [0|255] ""  MBMU
 SG_ I2A_Byrack_Info4_HW_Ver_Byte11 : 16|8@1+ (1,0) [0|255] ""  MBMU
 SG_ I2A_Byrack_Info4_HW_Ver_Byte12 : 24|8@1+ (1,0) [0|255] ""  MBMU
 SG_ I2A_Byrack_Info4_HW_Ver_Byte13 : 32|8@1+ (1,0) [0|255] ""  MBMU
 SG_ I2A_Byrack_Info4_HW_Ver_Byte14 : 40|8@1+ (1,0) [0|255] ""  MBMU
 SG_ I2A_Byrack_Info4_HW_Ver_Byte15 : 48|8@1+ (1,0) [0|255] ""  MBMU
 SG_ I2A_Byrack_Info4_HW_Ver_Byte16 : 56|8@1+ (1,0) [0|255] ""  MBMU

BO_ 2332156980 I2A_Byrack_info4__20: 8 IMM
 SG_ I2A_Byrack_Info4_HW_Ver_Byte9 : 0|8@1+ (1,0) [0|255] ""  MBMU
 SG_ I2A_Byrack_Info4_HW_Ver_Byte10 : 8|8@1+ (1,0) [0|255] ""  MBMU
 SG_ I2A_Byrack_Info4_HW_Ver_Byte11 : 16|8@1+ (1,0) [0|255] ""  MBMU
 SG_ I2A_Byrack_Info4_HW_Ver_Byte12 : 24|8@1+ (1,0) [0|255] ""  MBMU
 SG_ I2A_Byrack_Info4_HW_Ver_Byte13 : 32|8@1+ (1,0) [0|255] ""  MBMU
 SG_ I2A_Byrack_Info4_HW_Ver_Byte14 : 40|8@1+ (1,0) [0|255] ""  MBMU
 SG_ I2A_Byrack_Info4_HW_Ver_Byte15 : 48|8@1+ (1,0) [0|255] ""  MBMU
 SG_ I2A_Byrack_Info4_HW_Ver_Byte16 : 56|8@1+ (1,0) [0|255] ""  MBMU

BO_ 2332156981 I2A_Byrack_info4__21: 8 IMM
 SG_ I2A_Byrack_Info4_HW_Ver_Byte9 : 0|8@1+ (1,0) [0|255] ""  MBMU
 SG_ I2A_Byrack_Info4_HW_Ver_Byte10 : 8|8@1+ (1,0) [0|255] ""  MBMU
 SG_ I2A_Byrack_Info4_HW_Ver_Byte11 : 16|8@1+ (1,0) [0|255] ""  MBMU
 SG_ I2A_Byrack_Info4_HW_Ver_Byte12 : 24|8@1+ (1,0) [0|255] ""  MBMU
 SG_ I2A_Byrack_Info4_HW_Ver_Byte13 : 32|8@1+ (1,0) [0|255] ""  MBMU
 SG_ I2A_Byrack_Info4_HW_Ver_Byte14 : 40|8@1+ (1,0) [0|255] ""  MBMU
 SG_ I2A_Byrack_Info4_HW_Ver_Byte15 : 48|8@1+ (1,0) [0|255] ""  MBMU
 SG_ I2A_Byrack_Info4_HW_Ver_Byte16 : 56|8@1+ (1,0) [0|255] ""  MBMU

BO_ 2332156982 I2A_Byrack_info4__22: 8 IMM
 SG_ I2A_Byrack_Info4_HW_Ver_Byte9 : 0|8@1+ (1,0) [0|255] ""  MBMU
 SG_ I2A_Byrack_Info4_HW_Ver_Byte10 : 8|8@1+ (1,0) [0|255] ""  MBMU
 SG_ I2A_Byrack_Info4_HW_Ver_Byte11 : 16|8@1+ (1,0) [0|255] ""  MBMU
 SG_ I2A_Byrack_Info4_HW_Ver_Byte12 : 24|8@1+ (1,0) [0|255] ""  MBMU
 SG_ I2A_Byrack_Info4_HW_Ver_Byte13 : 32|8@1+ (1,0) [0|255] ""  MBMU
 SG_ I2A_Byrack_Info4_HW_Ver_Byte14 : 40|8@1+ (1,0) [0|255] ""  MBMU
 SG_ I2A_Byrack_Info4_HW_Ver_Byte15 : 48|8@1+ (1,0) [0|255] ""  MBMU
 SG_ I2A_Byrack_Info4_HW_Ver_Byte16 : 56|8@1+ (1,0) [0|255] ""  MBMU

BO_ 2332156983 I2A_Byrack_info4__23: 8 IMM
 SG_ I2A_Byrack_Info4_HW_Ver_Byte9 : 0|8@1+ (1,0) [0|255] ""  MBMU
 SG_ I2A_Byrack_Info4_HW_Ver_Byte10 : 8|8@1+ (1,0) [0|255] ""  MBMU
 SG_ I2A_Byrack_Info4_HW_Ver_Byte11 : 16|8@1+ (1,0) [0|255] ""  MBMU
 SG_ I2A_Byrack_Info4_HW_Ver_Byte12 : 24|8@1+ (1,0) [0|255] ""  MBMU
 SG_ I2A_Byrack_Info4_HW_Ver_Byte13 : 32|8@1+ (1,0) [0|255] ""  MBMU
 SG_ I2A_Byrack_Info4_HW_Ver_Byte14 : 40|8@1+ (1,0) [0|255] ""  MBMU
 SG_ I2A_Byrack_Info4_HW_Ver_Byte15 : 48|8@1+ (1,0) [0|255] ""  MBMU
 SG_ I2A_Byrack_Info4_HW_Ver_Byte16 : 56|8@1+ (1,0) [0|255] ""  MBMU

BO_ 2332156984 I2A_Byrack_info4__24: 8 IMM
 SG_ I2A_Byrack_Info4_HW_Ver_Byte9 : 0|8@1+ (1,0) [0|255] ""  MBMU
 SG_ I2A_Byrack_Info4_HW_Ver_Byte10 : 8|8@1+ (1,0) [0|255] ""  MBMU
 SG_ I2A_Byrack_Info4_HW_Ver_Byte11 : 16|8@1+ (1,0) [0|255] ""  MBMU
 SG_ I2A_Byrack_Info4_HW_Ver_Byte12 : 24|8@1+ (1,0) [0|255] ""  MBMU
 SG_ I2A_Byrack_Info4_HW_Ver_Byte13 : 32|8@1+ (1,0) [0|255] ""  MBMU
 SG_ I2A_Byrack_Info4_HW_Ver_Byte14 : 40|8@1+ (1,0) [0|255] ""  MBMU
 SG_ I2A_Byrack_Info4_HW_Ver_Byte15 : 48|8@1+ (1,0) [0|255] ""  MBMU
 SG_ I2A_Byrack_Info4_HW_Ver_Byte16 : 56|8@1+ (1,0) [0|255] ""  MBMU

BO_ 2332156985 I2A_Byrack_info4__25: 8 IMM
 SG_ I2A_Byrack_Info4_HW_Ver_Byte9 : 0|8@1+ (1,0) [0|255] ""  MBMU
 SG_ I2A_Byrack_Info4_HW_Ver_Byte10 : 8|8@1+ (1,0) [0|255] ""  MBMU
 SG_ I2A_Byrack_Info4_HW_Ver_Byte11 : 16|8@1+ (1,0) [0|255] ""  MBMU
 SG_ I2A_Byrack_Info4_HW_Ver_Byte12 : 24|8@1+ (1,0) [0|255] ""  MBMU
 SG_ I2A_Byrack_Info4_HW_Ver_Byte13 : 32|8@1+ (1,0) [0|255] ""  MBMU
 SG_ I2A_Byrack_Info4_HW_Ver_Byte14 : 40|8@1+ (1,0) [0|255] ""  MBMU
 SG_ I2A_Byrack_Info4_HW_Ver_Byte15 : 48|8@1+ (1,0) [0|255] ""  MBMU
 SG_ I2A_Byrack_Info4_HW_Ver_Byte16 : 56|8@1+ (1,0) [0|255] ""  MBMU

BO_ 2332156986 I2A_Byrack_info4__26: 8 IMM
 SG_ I2A_Byrack_Info4_HW_Ver_Byte9 : 0|8@1+ (1,0) [0|255] ""  MBMU
 SG_ I2A_Byrack_Info4_HW_Ver_Byte10 : 8|8@1+ (1,0) [0|255] ""  MBMU
 SG_ I2A_Byrack_Info4_HW_Ver_Byte11 : 16|8@1+ (1,0) [0|255] ""  MBMU
 SG_ I2A_Byrack_Info4_HW_Ver_Byte12 : 24|8@1+ (1,0) [0|255] ""  MBMU
 SG_ I2A_Byrack_Info4_HW_Ver_Byte13 : 32|8@1+ (1,0) [0|255] ""  MBMU
 SG_ I2A_Byrack_Info4_HW_Ver_Byte14 : 40|8@1+ (1,0) [0|255] ""  MBMU
 SG_ I2A_Byrack_Info4_HW_Ver_Byte15 : 48|8@1+ (1,0) [0|255] ""  MBMU
 SG_ I2A_Byrack_Info4_HW_Ver_Byte16 : 56|8@1+ (1,0) [0|255] ""  MBMU

BO_ 2332156987 I2A_Byrack_info4__27: 8 IMM
 SG_ I2A_Byrack_Info4_HW_Ver_Byte9 : 0|8@1+ (1,0) [0|255] ""  MBMU
 SG_ I2A_Byrack_Info4_HW_Ver_Byte10 : 8|8@1+ (1,0) [0|255] ""  MBMU
 SG_ I2A_Byrack_Info4_HW_Ver_Byte11 : 16|8@1+ (1,0) [0|255] ""  MBMU
 SG_ I2A_Byrack_Info4_HW_Ver_Byte12 : 24|8@1+ (1,0) [0|255] ""  MBMU
 SG_ I2A_Byrack_Info4_HW_Ver_Byte13 : 32|8@1+ (1,0) [0|255] ""  MBMU
 SG_ I2A_Byrack_Info4_HW_Ver_Byte14 : 40|8@1+ (1,0) [0|255] ""  MBMU
 SG_ I2A_Byrack_Info4_HW_Ver_Byte15 : 48|8@1+ (1,0) [0|255] ""  MBMU
 SG_ I2A_Byrack_Info4_HW_Ver_Byte16 : 56|8@1+ (1,0) [0|255] ""  MBMU

BO_ 2332156988 I2A_Byrack_info4__28: 8 IMM
 SG_ I2A_Byrack_Info4_HW_Ver_Byte9 : 0|8@1+ (1,0) [0|255] ""  MBMU
 SG_ I2A_Byrack_Info4_HW_Ver_Byte10 : 8|8@1+ (1,0) [0|255] ""  MBMU
 SG_ I2A_Byrack_Info4_HW_Ver_Byte11 : 16|8@1+ (1,0) [0|255] ""  MBMU
 SG_ I2A_Byrack_Info4_HW_Ver_Byte12 : 24|8@1+ (1,0) [0|255] ""  MBMU
 SG_ I2A_Byrack_Info4_HW_Ver_Byte13 : 32|8@1+ (1,0) [0|255] ""  MBMU
 SG_ I2A_Byrack_Info4_HW_Ver_Byte14 : 40|8@1+ (1,0) [0|255] ""  MBMU
 SG_ I2A_Byrack_Info4_HW_Ver_Byte15 : 48|8@1+ (1,0) [0|255] ""  MBMU
 SG_ I2A_Byrack_Info4_HW_Ver_Byte16 : 56|8@1+ (1,0) [0|255] ""  MBMU

BO_ 2332156989 I2A_Byrack_info4__29: 8 IMM
 SG_ I2A_Byrack_Info4_HW_Ver_Byte9 : 0|8@1+ (1,0) [0|255] ""  MBMU
 SG_ I2A_Byrack_Info4_HW_Ver_Byte10 : 8|8@1+ (1,0) [0|255] ""  MBMU
 SG_ I2A_Byrack_Info4_HW_Ver_Byte11 : 16|8@1+ (1,0) [0|255] ""  MBMU
 SG_ I2A_Byrack_Info4_HW_Ver_Byte12 : 24|8@1+ (1,0) [0|255] ""  MBMU
 SG_ I2A_Byrack_Info4_HW_Ver_Byte13 : 32|8@1+ (1,0) [0|255] ""  MBMU
 SG_ I2A_Byrack_Info4_HW_Ver_Byte14 : 40|8@1+ (1,0) [0|255] ""  MBMU
 SG_ I2A_Byrack_Info4_HW_Ver_Byte15 : 48|8@1+ (1,0) [0|255] ""  MBMU
 SG_ I2A_Byrack_Info4_HW_Ver_Byte16 : 56|8@1+ (1,0) [0|255] ""  MBMU

BO_ 2332156990 I2A_Byrack_info4__30: 8 IMM
 SG_ I2A_Byrack_Info4_HW_Ver_Byte9 : 0|8@1+ (1,0) [0|255] ""  MBMU
 SG_ I2A_Byrack_Info4_HW_Ver_Byte10 : 8|8@1+ (1,0) [0|255] ""  MBMU
 SG_ I2A_Byrack_Info4_HW_Ver_Byte11 : 16|8@1+ (1,0) [0|255] ""  MBMU
 SG_ I2A_Byrack_Info4_HW_Ver_Byte12 : 24|8@1+ (1,0) [0|255] ""  MBMU
 SG_ I2A_Byrack_Info4_HW_Ver_Byte13 : 32|8@1+ (1,0) [0|255] ""  MBMU
 SG_ I2A_Byrack_Info4_HW_Ver_Byte14 : 40|8@1+ (1,0) [0|255] ""  MBMU
 SG_ I2A_Byrack_Info4_HW_Ver_Byte15 : 48|8@1+ (1,0) [0|255] ""  MBMU
 SG_ I2A_Byrack_Info4_HW_Ver_Byte16 : 56|8@1+ (1,0) [0|255] ""  MBMU

BO_ 2332156991 I2A_Byrack_info4__31: 8 IMM
 SG_ I2A_Byrack_Info4_HW_Ver_Byte9 : 0|8@1+ (1,0) [0|255] ""  MBMU
 SG_ I2A_Byrack_Info4_HW_Ver_Byte10 : 8|8@1+ (1,0) [0|255] ""  MBMU
 SG_ I2A_Byrack_Info4_HW_Ver_Byte11 : 16|8@1+ (1,0) [0|255] ""  MBMU
 SG_ I2A_Byrack_Info4_HW_Ver_Byte12 : 24|8@1+ (1,0) [0|255] ""  MBMU
 SG_ I2A_Byrack_Info4_HW_Ver_Byte13 : 32|8@1+ (1,0) [0|255] ""  MBMU
 SG_ I2A_Byrack_Info4_HW_Ver_Byte14 : 40|8@1+ (1,0) [0|255] ""  MBMU
 SG_ I2A_Byrack_Info4_HW_Ver_Byte15 : 48|8@1+ (1,0) [0|255] ""  MBMU
 SG_ I2A_Byrack_Info4_HW_Ver_Byte16 : 56|8@1+ (1,0) [0|255] ""  MBMU

BO_ 2332157217 I2A_Byrack_info5__01: 8 IMM
 SG_ I2A_Byrack_Barcode1 : 0|8@1+ (1,0) [0|255] ""  MBMU
 SG_ I2A_Byrack_Barcode2 : 8|8@1+ (1,0) [0|255] ""  MBMU
 SG_ I2A_Byrack_Barcode3 : 16|8@1+ (1,0) [0|255] ""  MBMU
 SG_ I2A_Byrack_Barcode4 : 24|8@1+ (1,0) [0|255] ""  MBMU
 SG_ I2A_Byrack_Barcode5 : 32|8@1+ (1,0) [0|255] ""  MBMU
 SG_ I2A_Byrack_Barcode6 : 40|8@1+ (1,0) [0|255] ""  MBMU

BO_ 2332157218 I2A_Byrack_info5__02: 8 IMM
 SG_ I2A_Byrack_Barcode1 : 0|8@1+ (1,0) [0|255] ""  MBMU
 SG_ I2A_Byrack_Barcode2 : 8|8@1+ (1,0) [0|255] ""  MBMU
 SG_ I2A_Byrack_Barcode3 : 16|8@1+ (1,0) [0|255] ""  MBMU
 SG_ I2A_Byrack_Barcode4 : 24|8@1+ (1,0) [0|255] ""  MBMU
 SG_ I2A_Byrack_Barcode5 : 32|8@1+ (1,0) [0|255] ""  MBMU
 SG_ I2A_Byrack_Barcode6 : 40|8@1+ (1,0) [0|255] ""  MBMU

BO_ 2332157219 I2A_Byrack_info5__03: 8 IMM
 SG_ I2A_Byrack_Barcode1 : 0|8@1+ (1,0) [0|255] ""  MBMU
 SG_ I2A_Byrack_Barcode2 : 8|8@1+ (1,0) [0|255] ""  MBMU
 SG_ I2A_Byrack_Barcode3 : 16|8@1+ (1,0) [0|255] ""  MBMU
 SG_ I2A_Byrack_Barcode4 : 24|8@1+ (1,0) [0|255] ""  MBMU
 SG_ I2A_Byrack_Barcode5 : 32|8@1+ (1,0) [0|255] ""  MBMU
 SG_ I2A_Byrack_Barcode6 : 40|8@1+ (1,0) [0|255] ""  MBMU

BO_ 2332157220 I2A_Byrack_info5__04: 8 IMM
 SG_ I2A_Byrack_Barcode1 : 0|8@1+ (1,0) [0|255] ""  MBMU
 SG_ I2A_Byrack_Barcode2 : 8|8@1+ (1,0) [0|255] ""  MBMU
 SG_ I2A_Byrack_Barcode3 : 16|8@1+ (1,0) [0|255] ""  MBMU
 SG_ I2A_Byrack_Barcode4 : 24|8@1+ (1,0) [0|255] ""  MBMU
 SG_ I2A_Byrack_Barcode5 : 32|8@1+ (1,0) [0|255] ""  MBMU
 SG_ I2A_Byrack_Barcode6 : 40|8@1+ (1,0) [0|255] ""  MBMU

BO_ 2332157221 I2A_Byrack_info5__05: 8 IMM
 SG_ I2A_Byrack_Barcode1 : 0|8@1+ (1,0) [0|255] ""  MBMU
 SG_ I2A_Byrack_Barcode2 : 8|8@1+ (1,0) [0|255] ""  MBMU
 SG_ I2A_Byrack_Barcode3 : 16|8@1+ (1,0) [0|255] ""  MBMU
 SG_ I2A_Byrack_Barcode4 : 24|8@1+ (1,0) [0|255] ""  MBMU
 SG_ I2A_Byrack_Barcode5 : 32|8@1+ (1,0) [0|255] ""  MBMU
 SG_ I2A_Byrack_Barcode6 : 40|8@1+ (1,0) [0|255] ""  MBMU

BO_ 2332157222 I2A_Byrack_info5__06: 8 IMM
 SG_ I2A_Byrack_Barcode1 : 0|8@1+ (1,0) [0|255] ""  MBMU
 SG_ I2A_Byrack_Barcode2 : 8|8@1+ (1,0) [0|255] ""  MBMU
 SG_ I2A_Byrack_Barcode3 : 16|8@1+ (1,0) [0|255] ""  MBMU
 SG_ I2A_Byrack_Barcode4 : 24|8@1+ (1,0) [0|255] ""  MBMU
 SG_ I2A_Byrack_Barcode5 : 32|8@1+ (1,0) [0|255] ""  MBMU
 SG_ I2A_Byrack_Barcode6 : 40|8@1+ (1,0) [0|255] ""  MBMU

BO_ 2332157223 I2A_Byrack_info5__07: 8 IMM
 SG_ I2A_Byrack_Barcode1 : 0|8@1+ (1,0) [0|255] ""  MBMU
 SG_ I2A_Byrack_Barcode2 : 8|8@1+ (1,0) [0|255] ""  MBMU
 SG_ I2A_Byrack_Barcode3 : 16|8@1+ (1,0) [0|255] ""  MBMU
 SG_ I2A_Byrack_Barcode4 : 24|8@1+ (1,0) [0|255] ""  MBMU
 SG_ I2A_Byrack_Barcode5 : 32|8@1+ (1,0) [0|255] ""  MBMU
 SG_ I2A_Byrack_Barcode6 : 40|8@1+ (1,0) [0|255] ""  MBMU

BO_ 2332157224 I2A_Byrack_info5__08: 8 IMM
 SG_ I2A_Byrack_Barcode1 : 0|8@1+ (1,0) [0|255] ""  MBMU
 SG_ I2A_Byrack_Barcode2 : 8|8@1+ (1,0) [0|255] ""  MBMU
 SG_ I2A_Byrack_Barcode3 : 16|8@1+ (1,0) [0|255] ""  MBMU
 SG_ I2A_Byrack_Barcode4 : 24|8@1+ (1,0) [0|255] ""  MBMU
 SG_ I2A_Byrack_Barcode5 : 32|8@1+ (1,0) [0|255] ""  MBMU
 SG_ I2A_Byrack_Barcode6 : 40|8@1+ (1,0) [0|255] ""  MBMU

BO_ 2332157225 I2A_Byrack_info5__09: 8 IMM
 SG_ I2A_Byrack_Barcode1 : 0|8@1+ (1,0) [0|255] ""  MBMU
 SG_ I2A_Byrack_Barcode2 : 8|8@1+ (1,0) [0|255] ""  MBMU
 SG_ I2A_Byrack_Barcode3 : 16|8@1+ (1,0) [0|255] ""  MBMU
 SG_ I2A_Byrack_Barcode4 : 24|8@1+ (1,0) [0|255] ""  MBMU
 SG_ I2A_Byrack_Barcode5 : 32|8@1+ (1,0) [0|255] ""  MBMU
 SG_ I2A_Byrack_Barcode6 : 40|8@1+ (1,0) [0|255] ""  MBMU

BO_ 2332157226 I2A_Byrack_info5__10: 8 IMM
 SG_ I2A_Byrack_Barcode1 : 0|8@1+ (1,0) [0|255] ""  MBMU
 SG_ I2A_Byrack_Barcode2 : 8|8@1+ (1,0) [0|255] ""  MBMU
 SG_ I2A_Byrack_Barcode3 : 16|8@1+ (1,0) [0|255] ""  MBMU
 SG_ I2A_Byrack_Barcode4 : 24|8@1+ (1,0) [0|255] ""  MBMU
 SG_ I2A_Byrack_Barcode5 : 32|8@1+ (1,0) [0|255] ""  MBMU
 SG_ I2A_Byrack_Barcode6 : 40|8@1+ (1,0) [0|255] ""  MBMU

BO_ 2332157227 I2A_Byrack_info5__11: 8 IMM
 SG_ I2A_Byrack_Barcode1 : 0|8@1+ (1,0) [0|255] ""  MBMU
 SG_ I2A_Byrack_Barcode2 : 8|8@1+ (1,0) [0|255] ""  MBMU
 SG_ I2A_Byrack_Barcode3 : 16|8@1+ (1,0) [0|255] ""  MBMU
 SG_ I2A_Byrack_Barcode4 : 24|8@1+ (1,0) [0|255] ""  MBMU
 SG_ I2A_Byrack_Barcode5 : 32|8@1+ (1,0) [0|255] ""  MBMU
 SG_ I2A_Byrack_Barcode6 : 40|8@1+ (1,0) [0|255] ""  MBMU

BO_ 2332157228 I2A_Byrack_info5__12: 8 IMM
 SG_ I2A_Byrack_Barcode1 : 0|8@1+ (1,0) [0|255] ""  MBMU
 SG_ I2A_Byrack_Barcode2 : 8|8@1+ (1,0) [0|255] ""  MBMU
 SG_ I2A_Byrack_Barcode3 : 16|8@1+ (1,0) [0|255] ""  MBMU
 SG_ I2A_Byrack_Barcode4 : 24|8@1+ (1,0) [0|255] ""  MBMU
 SG_ I2A_Byrack_Barcode5 : 32|8@1+ (1,0) [0|255] ""  MBMU
 SG_ I2A_Byrack_Barcode6 : 40|8@1+ (1,0) [0|255] ""  MBMU

BO_ 2332157229 I2A_Byrack_info5__13: 8 IMM
 SG_ I2A_Byrack_Barcode1 : 0|8@1+ (1,0) [0|255] ""  MBMU
 SG_ I2A_Byrack_Barcode2 : 8|8@1+ (1,0) [0|255] ""  MBMU
 SG_ I2A_Byrack_Barcode3 : 16|8@1+ (1,0) [0|255] ""  MBMU
 SG_ I2A_Byrack_Barcode4 : 24|8@1+ (1,0) [0|255] ""  MBMU
 SG_ I2A_Byrack_Barcode5 : 32|8@1+ (1,0) [0|255] ""  MBMU
 SG_ I2A_Byrack_Barcode6 : 40|8@1+ (1,0) [0|255] ""  MBMU

BO_ 2332157230 I2A_Byrack_info5__14: 8 IMM
 SG_ I2A_Byrack_Barcode1 : 0|8@1+ (1,0) [0|255] ""  MBMU
 SG_ I2A_Byrack_Barcode2 : 8|8@1+ (1,0) [0|255] ""  MBMU
 SG_ I2A_Byrack_Barcode3 : 16|8@1+ (1,0) [0|255] ""  MBMU
 SG_ I2A_Byrack_Barcode4 : 24|8@1+ (1,0) [0|255] ""  MBMU
 SG_ I2A_Byrack_Barcode5 : 32|8@1+ (1,0) [0|255] ""  MBMU
 SG_ I2A_Byrack_Barcode6 : 40|8@1+ (1,0) [0|255] ""  MBMU

BO_ 2332157231 I2A_Byrack_info5__15: 8 IMM
 SG_ I2A_Byrack_Barcode1 : 0|8@1+ (1,0) [0|255] ""  MBMU
 SG_ I2A_Byrack_Barcode2 : 8|8@1+ (1,0) [0|255] ""  MBMU
 SG_ I2A_Byrack_Barcode3 : 16|8@1+ (1,0) [0|255] ""  MBMU
 SG_ I2A_Byrack_Barcode4 : 24|8@1+ (1,0) [0|255] ""  MBMU
 SG_ I2A_Byrack_Barcode5 : 32|8@1+ (1,0) [0|255] ""  MBMU
 SG_ I2A_Byrack_Barcode6 : 40|8@1+ (1,0) [0|255] ""  MBMU

BO_ 2332157232 I2A_Byrack_info5__16: 8 IMM
 SG_ I2A_Byrack_Barcode1 : 0|8@1+ (1,0) [0|255] ""  MBMU
 SG_ I2A_Byrack_Barcode2 : 8|8@1+ (1,0) [0|255] ""  MBMU
 SG_ I2A_Byrack_Barcode3 : 16|8@1+ (1,0) [0|255] ""  MBMU
 SG_ I2A_Byrack_Barcode4 : 24|8@1+ (1,0) [0|255] ""  MBMU
 SG_ I2A_Byrack_Barcode5 : 32|8@1+ (1,0) [0|255] ""  MBMU
 SG_ I2A_Byrack_Barcode6 : 40|8@1+ (1,0) [0|255] ""  MBMU

BO_ 2332157233 I2A_Byrack_info5__17: 8 IMM
 SG_ I2A_Byrack_Barcode1 : 0|8@1+ (1,0) [0|255] ""  MBMU
 SG_ I2A_Byrack_Barcode2 : 8|8@1+ (1,0) [0|255] ""  MBMU
 SG_ I2A_Byrack_Barcode3 : 16|8@1+ (1,0) [0|255] ""  MBMU
 SG_ I2A_Byrack_Barcode4 : 24|8@1+ (1,0) [0|255] ""  MBMU
 SG_ I2A_Byrack_Barcode5 : 32|8@1+ (1,0) [0|255] ""  MBMU
 SG_ I2A_Byrack_Barcode6 : 40|8@1+ (1,0) [0|255] ""  MBMU

BO_ 2332157234 I2A_Byrack_info5__18: 8 IMM
 SG_ I2A_Byrack_Barcode1 : 0|8@1+ (1,0) [0|255] ""  MBMU
 SG_ I2A_Byrack_Barcode2 : 8|8@1+ (1,0) [0|255] ""  MBMU
 SG_ I2A_Byrack_Barcode3 : 16|8@1+ (1,0) [0|255] ""  MBMU
 SG_ I2A_Byrack_Barcode4 : 24|8@1+ (1,0) [0|255] ""  MBMU
 SG_ I2A_Byrack_Barcode5 : 32|8@1+ (1,0) [0|255] ""  MBMU
 SG_ I2A_Byrack_Barcode6 : 40|8@1+ (1,0) [0|255] ""  MBMU

BO_ 2332157235 I2A_Byrack_info5__19: 8 IMM
 SG_ I2A_Byrack_Barcode1 : 0|8@1+ (1,0) [0|255] ""  MBMU
 SG_ I2A_Byrack_Barcode2 : 8|8@1+ (1,0) [0|255] ""  MBMU
 SG_ I2A_Byrack_Barcode3 : 16|8@1+ (1,0) [0|255] ""  MBMU
 SG_ I2A_Byrack_Barcode4 : 24|8@1+ (1,0) [0|255] ""  MBMU
 SG_ I2A_Byrack_Barcode5 : 32|8@1+ (1,0) [0|255] ""  MBMU
 SG_ I2A_Byrack_Barcode6 : 40|8@1+ (1,0) [0|255] ""  MBMU

BO_ 2332157236 I2A_Byrack_info5__20: 8 IMM
 SG_ I2A_Byrack_Barcode1 : 0|8@1+ (1,0) [0|255] ""  MBMU
 SG_ I2A_Byrack_Barcode2 : 8|8@1+ (1,0) [0|255] ""  MBMU
 SG_ I2A_Byrack_Barcode3 : 16|8@1+ (1,0) [0|255] ""  MBMU
 SG_ I2A_Byrack_Barcode4 : 24|8@1+ (1,0) [0|255] ""  MBMU
 SG_ I2A_Byrack_Barcode5 : 32|8@1+ (1,0) [0|255] ""  MBMU
 SG_ I2A_Byrack_Barcode6 : 40|8@1+ (1,0) [0|255] ""  MBMU

BO_ 2332157237 I2A_Byrack_info5__21: 8 IMM
 SG_ I2A_Byrack_Barcode1 : 0|8@1+ (1,0) [0|255] ""  MBMU
 SG_ I2A_Byrack_Barcode2 : 8|8@1+ (1,0) [0|255] ""  MBMU
 SG_ I2A_Byrack_Barcode3 : 16|8@1+ (1,0) [0|255] ""  MBMU
 SG_ I2A_Byrack_Barcode4 : 24|8@1+ (1,0) [0|255] ""  MBMU
 SG_ I2A_Byrack_Barcode5 : 32|8@1+ (1,0) [0|255] ""  MBMU
 SG_ I2A_Byrack_Barcode6 : 40|8@1+ (1,0) [0|255] ""  MBMU

BO_ 2332157238 I2A_Byrack_info5__22: 8 IMM
 SG_ I2A_Byrack_Barcode1 : 0|8@1+ (1,0) [0|255] ""  MBMU
 SG_ I2A_Byrack_Barcode2 : 8|8@1+ (1,0) [0|255] ""  MBMU
 SG_ I2A_Byrack_Barcode3 : 16|8@1+ (1,0) [0|255] ""  MBMU
 SG_ I2A_Byrack_Barcode4 : 24|8@1+ (1,0) [0|255] ""  MBMU
 SG_ I2A_Byrack_Barcode5 : 32|8@1+ (1,0) [0|255] ""  MBMU
 SG_ I2A_Byrack_Barcode6 : 40|8@1+ (1,0) [0|255] ""  MBMU

BO_ 2332157239 I2A_Byrack_info5__23: 8 IMM
 SG_ I2A_Byrack_Barcode1 : 0|8@1+ (1,0) [0|255] ""  MBMU
 SG_ I2A_Byrack_Barcode2 : 8|8@1+ (1,0) [0|255] ""  MBMU
 SG_ I2A_Byrack_Barcode3 : 16|8@1+ (1,0) [0|255] ""  MBMU
 SG_ I2A_Byrack_Barcode4 : 24|8@1+ (1,0) [0|255] ""  MBMU
 SG_ I2A_Byrack_Barcode5 : 32|8@1+ (1,0) [0|255] ""  MBMU
 SG_ I2A_Byrack_Barcode6 : 40|8@1+ (1,0) [0|255] ""  MBMU

BO_ 2332157240 I2A_Byrack_info5__24: 8 IMM
 SG_ I2A_Byrack_Barcode1 : 0|8@1+ (1,0) [0|255] ""  MBMU
 SG_ I2A_Byrack_Barcode2 : 8|8@1+ (1,0) [0|255] ""  MBMU
 SG_ I2A_Byrack_Barcode3 : 16|8@1+ (1,0) [0|255] ""  MBMU
 SG_ I2A_Byrack_Barcode4 : 24|8@1+ (1,0) [0|255] ""  MBMU
 SG_ I2A_Byrack_Barcode5 : 32|8@1+ (1,0) [0|255] ""  MBMU
 SG_ I2A_Byrack_Barcode6 : 40|8@1+ (1,0) [0|255] ""  MBMU

BO_ 2332157241 I2A_Byrack_info5__25: 8 IMM
 SG_ I2A_Byrack_Barcode1 : 0|8@1+ (1,0) [0|255] ""  MBMU
 SG_ I2A_Byrack_Barcode2 : 8|8@1+ (1,0) [0|255] ""  MBMU
 SG_ I2A_Byrack_Barcode3 : 16|8@1+ (1,0) [0|255] ""  MBMU
 SG_ I2A_Byrack_Barcode4 : 24|8@1+ (1,0) [0|255] ""  MBMU
 SG_ I2A_Byrack_Barcode5 : 32|8@1+ (1,0) [0|255] ""  MBMU
 SG_ I2A_Byrack_Barcode6 : 40|8@1+ (1,0) [0|255] ""  MBMU

BO_ 2332157242 I2A_Byrack_info5__26: 8 IMM
 SG_ I2A_Byrack_Barcode1 : 0|8@1+ (1,0) [0|255] ""  MBMU
 SG_ I2A_Byrack_Barcode2 : 8|8@1+ (1,0) [0|255] ""  MBMU
 SG_ I2A_Byrack_Barcode3 : 16|8@1+ (1,0) [0|255] ""  MBMU
 SG_ I2A_Byrack_Barcode4 : 24|8@1+ (1,0) [0|255] ""  MBMU
 SG_ I2A_Byrack_Barcode5 : 32|8@1+ (1,0) [0|255] ""  MBMU
 SG_ I2A_Byrack_Barcode6 : 40|8@1+ (1,0) [0|255] ""  MBMU

BO_ 2332157243 I2A_Byrack_info5__27: 8 IMM
 SG_ I2A_Byrack_Barcode1 : 0|8@1+ (1,0) [0|255] ""  MBMU
 SG_ I2A_Byrack_Barcode2 : 8|8@1+ (1,0) [0|255] ""  MBMU
 SG_ I2A_Byrack_Barcode3 : 16|8@1+ (1,0) [0|255] ""  MBMU
 SG_ I2A_Byrack_Barcode4 : 24|8@1+ (1,0) [0|255] ""  MBMU
 SG_ I2A_Byrack_Barcode5 : 32|8@1+ (1,0) [0|255] ""  MBMU
 SG_ I2A_Byrack_Barcode6 : 40|8@1+ (1,0) [0|255] ""  MBMU

BO_ 2332157244 I2A_Byrack_info5__28: 8 IMM
 SG_ I2A_Byrack_Barcode1 : 0|8@1+ (1,0) [0|255] ""  MBMU
 SG_ I2A_Byrack_Barcode2 : 8|8@1+ (1,0) [0|255] ""  MBMU
 SG_ I2A_Byrack_Barcode3 : 16|8@1+ (1,0) [0|255] ""  MBMU
 SG_ I2A_Byrack_Barcode4 : 24|8@1+ (1,0) [0|255] ""  MBMU
 SG_ I2A_Byrack_Barcode5 : 32|8@1+ (1,0) [0|255] ""  MBMU
 SG_ I2A_Byrack_Barcode6 : 40|8@1+ (1,0) [0|255] ""  MBMU

BO_ 2332157245 I2A_Byrack_info5__29: 8 IMM
 SG_ I2A_Byrack_Barcode1 : 0|8@1+ (1,0) [0|255] ""  MBMU
 SG_ I2A_Byrack_Barcode2 : 8|8@1+ (1,0) [0|255] ""  MBMU
 SG_ I2A_Byrack_Barcode3 : 16|8@1+ (1,0) [0|255] ""  MBMU
 SG_ I2A_Byrack_Barcode4 : 24|8@1+ (1,0) [0|255] ""  MBMU
 SG_ I2A_Byrack_Barcode5 : 32|8@1+ (1,0) [0|255] ""  MBMU
 SG_ I2A_Byrack_Barcode6 : 40|8@1+ (1,0) [0|255] ""  MBMU

BO_ 2332157246 I2A_Byrack_info5__30: 8 IMM
 SG_ I2A_Byrack_Barcode1 : 0|8@1+ (1,0) [0|255] ""  MBMU
 SG_ I2A_Byrack_Barcode2 : 8|8@1+ (1,0) [0|255] ""  MBMU
 SG_ I2A_Byrack_Barcode3 : 16|8@1+ (1,0) [0|255] ""  MBMU
 SG_ I2A_Byrack_Barcode4 : 24|8@1+ (1,0) [0|255] ""  MBMU
 SG_ I2A_Byrack_Barcode5 : 32|8@1+ (1,0) [0|255] ""  MBMU
 SG_ I2A_Byrack_Barcode6 : 40|8@1+ (1,0) [0|255] ""  MBMU

BO_ 2332157247 I2A_Byrack_info5__31: 8 IMM
 SG_ I2A_Byrack_Barcode1 : 0|8@1+ (1,0) [0|255] ""  MBMU
 SG_ I2A_Byrack_Barcode2 : 8|8@1+ (1,0) [0|255] ""  MBMU
 SG_ I2A_Byrack_Barcode3 : 16|8@1+ (1,0) [0|255] ""  MBMU
 SG_ I2A_Byrack_Barcode4 : 24|8@1+ (1,0) [0|255] ""  MBMU
 SG_ I2A_Byrack_Barcode5 : 32|8@1+ (1,0) [0|255] ""  MBMU
 SG_ I2A_Byrack_Barcode6 : 40|8@1+ (1,0) [0|255] ""  MBMU

BO_ 2333535889 M2P_SUMDATA15__01: 8 MBMU
 SG_ M2P_Measure_Vol_B1_01 : 0|16@1+ (0.1,0) [0|6553.5] "V"  PC,SBMU
 SG_ M2P_Current_B1_01 : 16|16@1+ (1,-20000) [-20000|45535] "A"  PC,SBMU
 SG_ M2P_PermitMaxCharge_I_B1_01 : 32|16@1+ (1,-20000) [-20000|45535] "A"  PC
 SG_ M2P_PermitMaxDisCharge_I_B1_01 : 48|16@1+ (1,-20000) [-20000|45535] "A"  PC

BO_ 2333535890 M2P_SUMDATA15__02: 8 MBMU
 SG_ M2P_Measure_Vol_B1_02 : 0|16@1+ (0.1,0) [0|6553.5] "V"  PC,SBMU
 SG_ M2P_Current_B1_02 : 16|16@1+ (1,-20000) [-20000|45535] "A"  PC,SBMU
 SG_ M2P_PermitMaxCharge_I_B1_02 : 32|16@1+ (1,-20000) [-20000|45535] "A"  PC
 SG_ M2P_PermitMaxDisCharge_I_B1_02 : 48|16@1+ (1,-20000) [-20000|45535] "A"  PC

BO_ 2333535891 M2P_SUMDATA15__03: 8 MBMU
 SG_ M2P_Measure_Vol_B1_03 : 0|16@1+ (0.1,0) [0|6553.5] "V"  PC,SBMU
 SG_ M2P_Current_B1_03 : 16|16@1+ (1,-20000) [-20000|45535] "A"  PC,SBMU
 SG_ M2P_PermitMaxCharge_I_B1_03 : 32|16@1+ (1,-20000) [-20000|45535] "A"  PC
 SG_ M2P_PermitMaxDisCharge_I_B1_03 : 48|16@1+ (1,-20000) [-20000|45535] "A"  PC

BO_ 2333535892 M2P_SUMDATA15__04: 8 MBMU
 SG_ M2P_Measure_Vol_B1_04 : 0|16@1+ (0.1,0) [0|6553.5] "V"  PC,SBMU
 SG_ M2P_Current_B1_04 : 16|16@1+ (1,-20000) [-20000|45535] "A"  PC,SBMU
 SG_ M2P_PermitMaxCharge_I_B1_04 : 32|16@1+ (1,-20000) [-20000|45535] "A"  PC
 SG_ M2P_PermitMaxDisCharge_I_B1_04 : 48|16@1+ (1,-20000) [-20000|45535] "A"  PC

BO_ 2333535893 M2P_SUMDATA15__05: 8 MBMU
 SG_ M2P_Measure_Vol_B1_05 : 0|16@1+ (0.1,0) [0|6553.5] "V"  PC,SBMU
 SG_ M2P_Current_B1_05 : 16|16@1+ (1,-20000) [-20000|45535] "A"  PC,SBMU
 SG_ M2P_PermitMaxCharge_I_B1_05 : 32|16@1+ (1,-20000) [-20000|45535] "A"  PC
 SG_ M2P_PermitMaxDisCharge_I_B1_05 : 48|16@1+ (1,-20000) [-20000|45535] "A"  PC

BO_ 2333535894 M2P_SUMDATA15__06: 8 MBMU
 SG_ M2P_Measure_Vol_B1_06 : 0|16@1+ (0.1,0) [0|6553.5] "V"  PC,SBMU
 SG_ M2P_Current_B1_06 : 16|16@1+ (1,-20000) [-20000|45535] "A"  PC,SBMU
 SG_ M2P_PermitMaxCharge_I_B1_06 : 32|16@1+ (1,-20000) [-20000|45535] "A"  PC
 SG_ M2P_PermitMaxDisCharge_I_B1_06 : 48|16@1+ (1,-20000) [-20000|45535] "A"  PC

BO_ 2333535895 M2P_SUMDATA15__07: 8 MBMU
 SG_ M2P_Measure_Vol_B1_07 : 0|16@1+ (0.1,0) [0|6553.5] "V"  PC,SBMU
 SG_ M2P_Current_B1_07 : 16|16@1+ (1,-20000) [-20000|45535] "A"  PC,SBMU
 SG_ M2P_PermitMaxCharge_I_B1_07 : 32|16@1+ (1,-20000) [-20000|45535] "A"  PC
 SG_ M2P_PermitMaxDisCharge_I_B1_07 : 48|16@1+ (1,-20000) [-20000|45535] "A"  PC

BO_ 2333535896 M2P_SUMDATA15__08: 8 MBMU
 SG_ M2P_Measure_Vol_B1_08 : 0|16@1+ (0.1,0) [0|6553.5] "V"  PC,SBMU
 SG_ M2P_Current_B1_08 : 16|16@1+ (1,-20000) [-20000|45535] "A"  PC,SBMU
 SG_ M2P_PermitMaxCharge_I_B1_08 : 32|16@1+ (1,-20000) [-20000|45535] "A"  PC
 SG_ M2P_PermitMaxDisCharge_I_B1_08 : 48|16@1+ (1,-20000) [-20000|45535] "A"  PC

BO_ 2333535897 M2P_SUMDATA15__09: 8 MBMU
 SG_ M2P_Measure_Vol_B1_09 : 0|16@1+ (0.1,0) [0|6553.5] "V"  PC,SBMU
 SG_ M2P_Current_B1_09 : 16|16@1+ (1,-20000) [-20000|45535] "A"  PC,SBMU
 SG_ M2P_PermitMaxCharge_I_B1_09 : 32|16@1+ (1,-20000) [-20000|45535] "A"  PC
 SG_ M2P_PermitMaxDisCharge_I_B1_09 : 48|16@1+ (1,-20000) [-20000|45535] "A"  PC

BO_ 2333535898 M2P_SUMDATA15__10: 8 MBMU
 SG_ M2P_Measure_Vol_B1_10 : 0|16@1+ (0.1,0) [0|6553.5] "V"  PC,SBMU
 SG_ M2P_Current_B1_10 : 16|16@1+ (1,-20000) [-20000|45535] "A"  PC,SBMU
 SG_ M2P_PermitMaxCharge_I_B1_10 : 32|16@1+ (1,-20000) [-20000|45535] "A"  PC
 SG_ M2P_PermitMaxDisCharge_I_B1_10 : 48|16@1+ (1,-20000) [-20000|45535] "A"  PC

BO_ 2333535899 M2P_SUMDATA15__11: 8 MBMU
 SG_ M2P_Measure_Vol_B1_11 : 0|16@1+ (0.1,0) [0|6553.5] "V"  PC,SBMU
 SG_ M2P_Current_B1_11 : 16|16@1+ (1,-20000) [-20000|45535] "A"  PC,SBMU
 SG_ M2P_PermitMaxCharge_I_B1_11 : 32|16@1+ (1,-20000) [-20000|45535] "A"  PC
 SG_ M2P_PermitMaxDisCharge_I_B1_11 : 48|16@1+ (1,-20000) [-20000|45535] "A"  PC

BO_ 2333535900 M2P_SUMDATA15__12: 8 MBMU
 SG_ M2P_Measure_Vol_B1_12 : 0|16@1+ (0.1,0) [0|6553.5] "V"  PC,SBMU
 SG_ M2P_Current_B1_12 : 16|16@1+ (1,-20000) [-20000|45535] "A"  PC,SBMU
 SG_ M2P_PermitMaxCharge_I_B1_12 : 32|16@1+ (1,-20000) [-20000|45535] "A"  PC
 SG_ M2P_PermitMaxDisCharge_I_B1_12 : 48|16@1+ (1,-20000) [-20000|45535] "A"  PC

BO_ 2333535901 M2P_SUMDATA15__13: 8 MBMU
 SG_ M2P_Measure_Vol_B1_13 : 0|16@1+ (0.1,0) [0|6553.5] "V"  PC,SBMU
 SG_ M2P_Current_B1_13 : 16|16@1+ (1,-20000) [-20000|45535] "A"  PC,SBMU
 SG_ M2P_PermitMaxCharge_I_B1_13 : 32|16@1+ (1,-20000) [-20000|45535] "A"  PC
 SG_ M2P_PermitMaxDisCharge_I_B1_13 : 48|16@1+ (1,-20000) [-20000|45535] "A"  PC

BO_ 2333535902 M2P_SUMDATA15__14: 8 MBMU
 SG_ M2P_Measure_Vol_B1_14 : 0|16@1+ (0.1,0) [0|6553.5] "V"  PC,SBMU
 SG_ M2P_Current_B1_14 : 16|16@1+ (1,-20000) [-20000|45535] "A"  PC,SBMU
 SG_ M2P_PermitMaxCharge_I_B1_14 : 32|16@1+ (1,-20000) [-20000|45535] "A"  PC
 SG_ M2P_PermitMaxDisCharge_I_B1_14 : 48|16@1+ (1,-20000) [-20000|45535] "A"  PC

BO_ 2333535903 M2P_SUMDATA15__15: 8 MBMU
 SG_ M2P_Measure_Vol_B1_15 : 0|16@1+ (0.1,0) [0|6553.5] "V"  PC,SBMU
 SG_ M2P_Current_B1_15 : 16|16@1+ (1,-20000) [-20000|45535] "A"  PC,SBMU
 SG_ M2P_PermitMaxCharge_I_B1_15 : 32|16@1+ (1,-20000) [-20000|45535] "A"  PC
 SG_ M2P_PermitMaxDisCharge_I_B1_15 : 48|16@1+ (1,-20000) [-20000|45535] "A"  PC

BO_ 2333535904 M2P_SUMDATA15__16: 8 MBMU
 SG_ M2P_Measure_Vol_B1_16 : 0|16@1+ (0.1,0) [0|6553.5] "V"  PC,SBMU
 SG_ M2P_Current_B1_16 : 16|16@1+ (1,-20000) [-20000|45535] "A"  PC,SBMU
 SG_ M2P_PermitMaxCharge_I_B1_16 : 32|16@1+ (1,-20000) [-20000|45535] "A"  PC
 SG_ M2P_PermitMaxDisCharge_I_B1_16 : 48|16@1+ (1,-20000) [-20000|45535] "A"  PC

BO_ 2333535905 M2P_SUMDATA15__17: 8 MBMU
 SG_ M2P_Measure_Vol_B1_17 : 0|16@1+ (0.1,0) [0|6553.5] "V"  PC,SBMU
 SG_ M2P_Current_B1_17 : 16|16@1+ (1,-20000) [-20000|45535] "A"  PC,SBMU
 SG_ M2P_PermitMaxCharge_I_B1_17 : 32|16@1+ (1,-20000) [-20000|45535] "A"  PC
 SG_ M2P_PermitMaxDisCharge_I_B1_17 : 48|16@1+ (1,-20000) [-20000|45535] "A"  PC

BO_ 2333535906 M2P_SUMDATA15__18: 8 MBMU
 SG_ M2P_Measure_Vol_B1_18 : 0|16@1+ (0.1,0) [0|6553.5] "V"  PC,SBMU
 SG_ M2P_Current_B1_18 : 16|16@1+ (1,-20000) [-20000|45535] "A"  PC,SBMU
 SG_ M2P_PermitMaxCharge_I_B1_18 : 32|16@1+ (1,-20000) [-20000|45535] "A"  PC
 SG_ M2P_PermitMaxDisCharge_I_B1_18 : 48|16@1+ (1,-20000) [-20000|45535] "A"  PC

BO_ 2333535907 M2P_SUMDATA15__19: 8 MBMU
 SG_ M2P_Measure_Vol_B1_19 : 0|16@1+ (0.1,0) [0|6553.5] "V"  PC,SBMU
 SG_ M2P_Current_B1_19 : 16|16@1+ (1,-20000) [-20000|45535] "A"  PC,SBMU
 SG_ M2P_PermitMaxCharge_I_B1_19 : 32|16@1+ (1,-20000) [-20000|45535] "A"  PC
 SG_ M2P_PermitMaxDisCharge_I_B1_19 : 48|16@1+ (1,-20000) [-20000|45535] "A"  PC

BO_ 2333535908 M2P_SUMDATA15__20: 8 MBMU
 SG_ M2P_Measure_Vol_B1_20 : 0|16@1+ (0.1,0) [0|6553.5] "V"  PC,SBMU
 SG_ M2P_Current_B1_20 : 16|16@1+ (1,-20000) [-20000|45535] "A"  PC,SBMU
 SG_ M2P_PermitMaxCharge_I_B1_20 : 32|16@1+ (1,-20000) [-20000|45535] "A"  PC
 SG_ M2P_PermitMaxDisCharge_I_B1_20 : 48|16@1+ (1,-20000) [-20000|45535] "A"  PC

BO_ 2333535909 M2P_SUMDATA15__21: 8 MBMU
 SG_ M2P_Measure_Vol_B1_21 : 0|16@1+ (0.1,0) [0|6553.5] "V"  PC,SBMU
 SG_ M2P_Current_B1_21 : 16|16@1+ (1,-20000) [-20000|45535] "A"  PC,SBMU
 SG_ M2P_PermitMaxCharge_I_B1_21 : 32|16@1+ (1,-20000) [-20000|45535] "A"  PC
 SG_ M2P_PermitMaxDisCharge_I_B1_21 : 48|16@1+ (1,-20000) [-20000|45535] "A"  PC

BO_ 2333535910 M2P_SUMDATA15__22: 8 MBMU
 SG_ M2P_Measure_Vol_B1_22 : 0|16@1+ (0.1,0) [0|6553.5] "V"  PC,SBMU
 SG_ M2P_Current_B1_22 : 16|16@1+ (1,-20000) [-20000|45535] "A"  PC,SBMU
 SG_ M2P_PermitMaxCharge_I_B1_22 : 32|16@1+ (1,-20000) [-20000|45535] "A"  PC
 SG_ M2P_PermitMaxDisCharge_I_B1_22 : 48|16@1+ (1,-20000) [-20000|45535] "A"  PC

BO_ 2333535911 M2P_SUMDATA15__23: 8 MBMU
 SG_ M2P_Measure_Vol_B1_23 : 0|16@1+ (0.1,0) [0|6553.5] "V"  PC,SBMU
 SG_ M2P_Current_B1_23 : 16|16@1+ (1,-20000) [-20000|45535] "A"  PC,SBMU
 SG_ M2P_PermitMaxCharge_I_B1_23 : 32|16@1+ (1,-20000) [-20000|45535] "A"  PC
 SG_ M2P_PermitMaxDisCharge_I_B1_23 : 48|16@1+ (1,-20000) [-20000|45535] "A"  PC

BO_ 2333535912 M2P_SUMDATA15__24: 8 MBMU
 SG_ M2P_Measure_Vol_B1_24 : 0|16@1+ (0.1,0) [0|6553.5] "V"  PC,SBMU
 SG_ M2P_Current_B1_24 : 16|16@1+ (1,-20000) [-20000|45535] "A"  PC,SBMU
 SG_ M2P_PermitMaxCharge_I_B1_24 : 32|16@1+ (1,-20000) [-20000|45535] "A"  PC
 SG_ M2P_PermitMaxDisCharge_I_B1_24 : 48|16@1+ (1,-20000) [-20000|45535] "A"  PC

BO_ 2333535913 M2P_SUMDATA15__25: 8 MBMU
 SG_ M2P_Measure_Vol_B1_25 : 0|16@1+ (0.1,0) [0|6553.5] "V"  PC,SBMU
 SG_ M2P_Current_B1_25 : 16|16@1+ (1,-20000) [-20000|45535] "A"  PC,SBMU
 SG_ M2P_PermitMaxCharge_I_B1_25 : 32|16@1+ (1,-20000) [-20000|45535] "A"  PC
 SG_ M2P_PermitMaxDisCharge_I_B1_25 : 48|16@1+ (1,-20000) [-20000|45535] "A"  PC

BO_ 2333535914 M2P_SUMDATA15__26: 8 MBMU
 SG_ M2P_Measure_Vol_B1_26 : 0|16@1+ (0.1,0) [0|6553.5] "V"  PC,SBMU
 SG_ M2P_Current_B1_26 : 16|16@1+ (1,-20000) [-20000|45535] "A"  PC,SBMU
 SG_ M2P_PermitMaxCharge_I_B1_26 : 32|16@1+ (1,-20000) [-20000|45535] "A"  PC
 SG_ M2P_PermitMaxDisCharge_I_B1_26 : 48|16@1+ (1,-20000) [-20000|45535] "A"  PC

BO_ 2333535915 M2P_SUMDATA15__27: 8 MBMU
 SG_ M2P_Measure_Vol_B1_27 : 0|16@1+ (0.1,0) [0|6553.5] "V"  PC,SBMU
 SG_ M2P_Current_B1_27 : 16|16@1+ (1,-20000) [-20000|45535] "A"  PC,SBMU
 SG_ M2P_PermitMaxCharge_I_B1_27 : 32|16@1+ (1,-20000) [-20000|45535] "A"  PC
 SG_ M2P_PermitMaxDisCharge_I_B1_27 : 48|16@1+ (1,-20000) [-20000|45535] "A"  PC

BO_ 2333535916 M2P_SUMDATA15__28: 8 MBMU
 SG_ M2P_Measure_Vol_B1_28 : 0|16@1+ (0.1,0) [0|6553.5] "V"  PC,SBMU
 SG_ M2P_Current_B1_28 : 16|16@1+ (1,-20000) [-20000|45535] "A"  PC,SBMU
 SG_ M2P_PermitMaxCharge_I_B1_28 : 32|16@1+ (1,-20000) [-20000|45535] "A"  PC
 SG_ M2P_PermitMaxDisCharge_I_B1_28 : 48|16@1+ (1,-20000) [-20000|45535] "A"  PC

CM_ SG_ 2333077148 Reserved_12 "预留";
CM_ SG_ 2333077149 Reserved_13 "预留";
CM_ SG_ 2333077150 Reserved_14 "预留";
CM_ SG_ 2333077151 Reserved_15 "预留";
CM_ SG_ 2333077152 Reserved_16 "预留";
CM_ SG_ 2333077153 Reserved_17 "预留";
CM_ SG_ 2333077154 Reserved_18 "预留";
CM_ SG_ 2333077155 Reserved_19 "预留";
CM_ SG_ 2333077156 Reserved_20 "预留";
CM_ SG_ 2333077157 Reserved_21 "预留";
CM_ SG_ 2333077158 Reserved_22 "预留";
CM_ SG_ 2333077159 Reserved_23 "预留";
CM_ SG_ 2333077160 Reserved_24 "预留";
CM_ SG_ 2333077161 Reserved_25 "预留";
CM_ SG_ 2333077162 Reserved_26 "预留";
CM_ SG_ 2333077163 Reserved_27 "预留";
CM_ SG_ 2333077164 Reserved_28 "预留";
CM_ SG_ 2333077165 Reserved_29 "预留";
CM_ SG_ 2333077166 Reserved_30 "预留";
CM_ SG_ 2333077167 Reserved_31 "预留";
CM_ SG_ 2332156193 I2A_Byrack_Info1_SW_Ver_Byte1 "IMM软件版本字节1";
CM_ SG_ 2332156193 I2A_Byrack_Info1_SW_Ver_Byte2 "IMM软件版本字节2";
CM_ SG_ 2332156193 I2A_Byrack_Info1_SW_Ver_Byte3 "IMM软件版本字节3";
CM_ SG_ 2332156193 I2A_Byrack_Info1_SW_Ver_Byte4 "IMM软件版本字节4";
CM_ SG_ 2332156193 I2A_Byrack_Info1_SW_Ver_Byte5 "IMM软件版本字节5";
CM_ SG_ 2332156193 I2A_Byrack_Info1_SW_Ver_Byte6 "IMM软件版本字节6";
CM_ SG_ 2332156193 I2A_Byrack_Info1_SW_Ver_Byte7 "IMM软件版本字节7";
CM_ SG_ 2332156193 I2A_Byrack_Info1_SW_Ver_Byte8 "IMM软件版本字节8";
CM_ SG_ 2332156194 I2A_Byrack_Info1_SW_Ver_Byte1 "IMM软件版本字节1";
CM_ SG_ 2332156194 I2A_Byrack_Info1_SW_Ver_Byte2 "IMM软件版本字节2";
CM_ SG_ 2332156194 I2A_Byrack_Info1_SW_Ver_Byte3 "IMM软件版本字节3";
CM_ SG_ 2332156194 I2A_Byrack_Info1_SW_Ver_Byte4 "IMM软件版本字节4";
CM_ SG_ 2332156194 I2A_Byrack_Info1_SW_Ver_Byte5 "IMM软件版本字节5";
CM_ SG_ 2332156194 I2A_Byrack_Info1_SW_Ver_Byte6 "IMM软件版本字节6";
CM_ SG_ 2332156194 I2A_Byrack_Info1_SW_Ver_Byte7 "IMM软件版本字节7";
CM_ SG_ 2332156194 I2A_Byrack_Info1_SW_Ver_Byte8 "IMM软件版本字节8";
CM_ SG_ 2332156195 I2A_Byrack_Info1_SW_Ver_Byte1 "IMM软件版本字节1";
CM_ SG_ 2332156195 I2A_Byrack_Info1_SW_Ver_Byte2 "IMM软件版本字节2";
CM_ SG_ 2332156195 I2A_Byrack_Info1_SW_Ver_Byte3 "IMM软件版本字节3";
CM_ SG_ 2332156195 I2A_Byrack_Info1_SW_Ver_Byte4 "IMM软件版本字节4";
CM_ SG_ 2332156195 I2A_Byrack_Info1_SW_Ver_Byte5 "IMM软件版本字节5";
CM_ SG_ 2332156195 I2A_Byrack_Info1_SW_Ver_Byte6 "IMM软件版本字节6";
CM_ SG_ 2332156195 I2A_Byrack_Info1_SW_Ver_Byte7 "IMM软件版本字节7";
CM_ SG_ 2332156195 I2A_Byrack_Info1_SW_Ver_Byte8 "IMM软件版本字节8";
CM_ SG_ 2332156196 I2A_Byrack_Info1_SW_Ver_Byte1 "IMM软件版本字节1";
CM_ SG_ 2332156196 I2A_Byrack_Info1_SW_Ver_Byte2 "IMM软件版本字节2";
CM_ SG_ 2332156196 I2A_Byrack_Info1_SW_Ver_Byte3 "IMM软件版本字节3";
CM_ SG_ 2332156196 I2A_Byrack_Info1_SW_Ver_Byte4 "IMM软件版本字节4";
CM_ SG_ 2332156196 I2A_Byrack_Info1_SW_Ver_Byte5 "IMM软件版本字节5";
CM_ SG_ 2332156196 I2A_Byrack_Info1_SW_Ver_Byte6 "IMM软件版本字节6";
CM_ SG_ 2332156196 I2A_Byrack_Info1_SW_Ver_Byte7 "IMM软件版本字节7";
CM_ SG_ 2332156196 I2A_Byrack_Info1_SW_Ver_Byte8 "IMM软件版本字节8";
CM_ SG_ 2332156197 I2A_Byrack_Info1_SW_Ver_Byte1 "IMM软件版本字节1";
CM_ SG_ 2332156197 I2A_Byrack_Info1_SW_Ver_Byte2 "IMM软件版本字节2";
CM_ SG_ 2332156197 I2A_Byrack_Info1_SW_Ver_Byte3 "IMM软件版本字节3";
CM_ SG_ 2332156197 I2A_Byrack_Info1_SW_Ver_Byte4 "IMM软件版本字节4";
CM_ SG_ 2332156197 I2A_Byrack_Info1_SW_Ver_Byte5 "IMM软件版本字节5";
CM_ SG_ 2332156197 I2A_Byrack_Info1_SW_Ver_Byte6 "IMM软件版本字节6";
CM_ SG_ 2332156197 I2A_Byrack_Info1_SW_Ver_Byte7 "IMM软件版本字节7";
CM_ SG_ 2332156197 I2A_Byrack_Info1_SW_Ver_Byte8 "IMM软件版本字节8";
CM_ SG_ 2332156198 I2A_Byrack_Info1_SW_Ver_Byte1 "IMM软件版本字节1";
CM_ SG_ 2332156198 I2A_Byrack_Info1_SW_Ver_Byte2 "IMM软件版本字节2";
CM_ SG_ 2332156198 I2A_Byrack_Info1_SW_Ver_Byte3 "IMM软件版本字节3";
CM_ SG_ 2332156198 I2A_Byrack_Info1_SW_Ver_Byte4 "IMM软件版本字节4";
CM_ SG_ 2332156198 I2A_Byrack_Info1_SW_Ver_Byte5 "IMM软件版本字节5";
CM_ SG_ 2332156198 I2A_Byrack_Info1_SW_Ver_Byte6 "IMM软件版本字节6";
CM_ SG_ 2332156198 I2A_Byrack_Info1_SW_Ver_Byte7 "IMM软件版本字节7";
CM_ SG_ 2332156198 I2A_Byrack_Info1_SW_Ver_Byte8 "IMM软件版本字节8";
CM_ SG_ 2332156199 I2A_Byrack_Info1_SW_Ver_Byte1 "IMM软件版本字节1";
CM_ SG_ 2332156199 I2A_Byrack_Info1_SW_Ver_Byte2 "IMM软件版本字节2";
CM_ SG_ 2332156199 I2A_Byrack_Info1_SW_Ver_Byte3 "IMM软件版本字节3";
CM_ SG_ 2332156199 I2A_Byrack_Info1_SW_Ver_Byte4 "IMM软件版本字节4";
CM_ SG_ 2332156199 I2A_Byrack_Info1_SW_Ver_Byte5 "IMM软件版本字节5";
CM_ SG_ 2332156199 I2A_Byrack_Info1_SW_Ver_Byte6 "IMM软件版本字节6";
CM_ SG_ 2332156199 I2A_Byrack_Info1_SW_Ver_Byte7 "IMM软件版本字节7";
CM_ SG_ 2332156199 I2A_Byrack_Info1_SW_Ver_Byte8 "IMM软件版本字节8";
CM_ SG_ 2332156200 I2A_Byrack_Info1_SW_Ver_Byte1 "IMM软件版本字节1";
CM_ SG_ 2332156200 I2A_Byrack_Info1_SW_Ver_Byte2 "IMM软件版本字节2";
CM_ SG_ 2332156200 I2A_Byrack_Info1_SW_Ver_Byte3 "IMM软件版本字节3";
CM_ SG_ 2332156200 I2A_Byrack_Info1_SW_Ver_Byte4 "IMM软件版本字节4";
CM_ SG_ 2332156200 I2A_Byrack_Info1_SW_Ver_Byte5 "IMM软件版本字节5";
CM_ SG_ 2332156200 I2A_Byrack_Info1_SW_Ver_Byte6 "IMM软件版本字节6";
CM_ SG_ 2332156200 I2A_Byrack_Info1_SW_Ver_Byte7 "IMM软件版本字节7";
CM_ SG_ 2332156200 I2A_Byrack_Info1_SW_Ver_Byte8 "IMM软件版本字节8";
CM_ SG_ 2332156201 I2A_Byrack_Info1_SW_Ver_Byte1 "IMM软件版本字节1";
CM_ SG_ 2332156201 I2A_Byrack_Info1_SW_Ver_Byte2 "IMM软件版本字节2";
CM_ SG_ 2332156201 I2A_Byrack_Info1_SW_Ver_Byte3 "IMM软件版本字节3";
CM_ SG_ 2332156201 I2A_Byrack_Info1_SW_Ver_Byte4 "IMM软件版本字节4";
CM_ SG_ 2332156201 I2A_Byrack_Info1_SW_Ver_Byte5 "IMM软件版本字节5";
CM_ SG_ 2332156201 I2A_Byrack_Info1_SW_Ver_Byte6 "IMM软件版本字节6";
CM_ SG_ 2332156201 I2A_Byrack_Info1_SW_Ver_Byte7 "IMM软件版本字节7";
CM_ SG_ 2332156201 I2A_Byrack_Info1_SW_Ver_Byte8 "IMM软件版本字节8";
CM_ SG_ 2332156202 I2A_Byrack_Info1_SW_Ver_Byte1 "IMM软件版本字节1";
CM_ SG_ 2332156202 I2A_Byrack_Info1_SW_Ver_Byte2 "IMM软件版本字节2";
CM_ SG_ 2332156202 I2A_Byrack_Info1_SW_Ver_Byte3 "IMM软件版本字节3";
CM_ SG_ 2332156202 I2A_Byrack_Info1_SW_Ver_Byte4 "IMM软件版本字节4";
CM_ SG_ 2332156202 I2A_Byrack_Info1_SW_Ver_Byte5 "IMM软件版本字节5";
CM_ SG_ 2332156202 I2A_Byrack_Info1_SW_Ver_Byte6 "IMM软件版本字节6";
CM_ SG_ 2332156202 I2A_Byrack_Info1_SW_Ver_Byte7 "IMM软件版本字节7";
CM_ SG_ 2332156202 I2A_Byrack_Info1_SW_Ver_Byte8 "IMM软件版本字节8";
CM_ SG_ 2332156203 I2A_Byrack_Info1_SW_Ver_Byte1 "IMM软件版本字节1";
CM_ SG_ 2332156203 I2A_Byrack_Info1_SW_Ver_Byte2 "IMM软件版本字节2";
CM_ SG_ 2332156203 I2A_Byrack_Info1_SW_Ver_Byte3 "IMM软件版本字节3";
CM_ SG_ 2332156203 I2A_Byrack_Info1_SW_Ver_Byte4 "IMM软件版本字节4";
CM_ SG_ 2332156203 I2A_Byrack_Info1_SW_Ver_Byte5 "IMM软件版本字节5";
CM_ SG_ 2332156203 I2A_Byrack_Info1_SW_Ver_Byte6 "IMM软件版本字节6";
CM_ SG_ 2332156203 I2A_Byrack_Info1_SW_Ver_Byte7 "IMM软件版本字节7";
CM_ SG_ 2332156203 I2A_Byrack_Info1_SW_Ver_Byte8 "IMM软件版本字节8";
CM_ SG_ 2332156204 I2A_Byrack_Info1_SW_Ver_Byte1 "IMM软件版本字节1";
CM_ SG_ 2332156204 I2A_Byrack_Info1_SW_Ver_Byte2 "IMM软件版本字节2";
CM_ SG_ 2332156204 I2A_Byrack_Info1_SW_Ver_Byte3 "IMM软件版本字节3";
CM_ SG_ 2332156204 I2A_Byrack_Info1_SW_Ver_Byte4 "IMM软件版本字节4";
CM_ SG_ 2332156204 I2A_Byrack_Info1_SW_Ver_Byte5 "IMM软件版本字节5";
CM_ SG_ 2332156204 I2A_Byrack_Info1_SW_Ver_Byte6 "IMM软件版本字节6";
CM_ SG_ 2332156204 I2A_Byrack_Info1_SW_Ver_Byte7 "IMM软件版本字节7";
CM_ SG_ 2332156204 I2A_Byrack_Info1_SW_Ver_Byte8 "IMM软件版本字节8";
CM_ SG_ 2332156205 I2A_Byrack_Info1_SW_Ver_Byte1 "IMM软件版本字节1";
CM_ SG_ 2332156205 I2A_Byrack_Info1_SW_Ver_Byte2 "IMM软件版本字节2";
CM_ SG_ 2332156205 I2A_Byrack_Info1_SW_Ver_Byte3 "IMM软件版本字节3";
CM_ SG_ 2332156205 I2A_Byrack_Info1_SW_Ver_Byte4 "IMM软件版本字节4";
CM_ SG_ 2332156205 I2A_Byrack_Info1_SW_Ver_Byte5 "IMM软件版本字节5";
CM_ SG_ 2332156205 I2A_Byrack_Info1_SW_Ver_Byte6 "IMM软件版本字节6";
CM_ SG_ 2332156205 I2A_Byrack_Info1_SW_Ver_Byte7 "IMM软件版本字节7";
CM_ SG_ 2332156205 I2A_Byrack_Info1_SW_Ver_Byte8 "IMM软件版本字节8";
CM_ SG_ 2332156206 I2A_Byrack_Info1_SW_Ver_Byte1 "IMM软件版本字节1";
CM_ SG_ 2332156206 I2A_Byrack_Info1_SW_Ver_Byte2 "IMM软件版本字节2";
CM_ SG_ 2332156206 I2A_Byrack_Info1_SW_Ver_Byte3 "IMM软件版本字节3";
CM_ SG_ 2332156206 I2A_Byrack_Info1_SW_Ver_Byte4 "IMM软件版本字节4";
CM_ SG_ 2332156206 I2A_Byrack_Info1_SW_Ver_Byte5 "IMM软件版本字节5";
CM_ SG_ 2332156206 I2A_Byrack_Info1_SW_Ver_Byte6 "IMM软件版本字节6";
CM_ SG_ 2332156206 I2A_Byrack_Info1_SW_Ver_Byte7 "IMM软件版本字节7";
CM_ SG_ 2332156206 I2A_Byrack_Info1_SW_Ver_Byte8 "IMM软件版本字节8";
CM_ SG_ 2332156207 I2A_Byrack_Info1_SW_Ver_Byte1 "IMM软件版本字节1";
CM_ SG_ 2332156207 I2A_Byrack_Info1_SW_Ver_Byte2 "IMM软件版本字节2";
CM_ SG_ 2332156207 I2A_Byrack_Info1_SW_Ver_Byte3 "IMM软件版本字节3";
CM_ SG_ 2332156207 I2A_Byrack_Info1_SW_Ver_Byte4 "IMM软件版本字节4";
CM_ SG_ 2332156207 I2A_Byrack_Info1_SW_Ver_Byte5 "IMM软件版本字节5";
CM_ SG_ 2332156207 I2A_Byrack_Info1_SW_Ver_Byte6 "IMM软件版本字节6";
CM_ SG_ 2332156207 I2A_Byrack_Info1_SW_Ver_Byte7 "IMM软件版本字节7";
CM_ SG_ 2332156207 I2A_Byrack_Info1_SW_Ver_Byte8 "IMM软件版本字节8";
CM_ SG_ 2332156208 I2A_Byrack_Info1_SW_Ver_Byte1 "IMM软件版本字节1";
CM_ SG_ 2332156208 I2A_Byrack_Info1_SW_Ver_Byte2 "IMM软件版本字节2";
CM_ SG_ 2332156208 I2A_Byrack_Info1_SW_Ver_Byte3 "IMM软件版本字节3";
CM_ SG_ 2332156208 I2A_Byrack_Info1_SW_Ver_Byte4 "IMM软件版本字节4";
CM_ SG_ 2332156208 I2A_Byrack_Info1_SW_Ver_Byte5 "IMM软件版本字节5";
CM_ SG_ 2332156208 I2A_Byrack_Info1_SW_Ver_Byte6 "IMM软件版本字节6";
CM_ SG_ 2332156208 I2A_Byrack_Info1_SW_Ver_Byte7 "IMM软件版本字节7";
CM_ SG_ 2332156208 I2A_Byrack_Info1_SW_Ver_Byte8 "IMM软件版本字节8";
CM_ SG_ 2332156209 I2A_Byrack_Info1_SW_Ver_Byte1 "IMM软件版本字节1";
CM_ SG_ 2332156209 I2A_Byrack_Info1_SW_Ver_Byte2 "IMM软件版本字节2";
CM_ SG_ 2332156209 I2A_Byrack_Info1_SW_Ver_Byte3 "IMM软件版本字节3";
CM_ SG_ 2332156209 I2A_Byrack_Info1_SW_Ver_Byte4 "IMM软件版本字节4";
CM_ SG_ 2332156209 I2A_Byrack_Info1_SW_Ver_Byte5 "IMM软件版本字节5";
CM_ SG_ 2332156209 I2A_Byrack_Info1_SW_Ver_Byte6 "IMM软件版本字节6";
CM_ SG_ 2332156209 I2A_Byrack_Info1_SW_Ver_Byte7 "IMM软件版本字节7";
CM_ SG_ 2332156209 I2A_Byrack_Info1_SW_Ver_Byte8 "IMM软件版本字节8";
CM_ SG_ 2332156210 I2A_Byrack_Info1_SW_Ver_Byte1 "IMM软件版本字节1";
CM_ SG_ 2332156210 I2A_Byrack_Info1_SW_Ver_Byte2 "IMM软件版本字节2";
CM_ SG_ 2332156210 I2A_Byrack_Info1_SW_Ver_Byte3 "IMM软件版本字节3";
CM_ SG_ 2332156210 I2A_Byrack_Info1_SW_Ver_Byte4 "IMM软件版本字节4";
CM_ SG_ 2332156210 I2A_Byrack_Info1_SW_Ver_Byte5 "IMM软件版本字节5";
CM_ SG_ 2332156210 I2A_Byrack_Info1_SW_Ver_Byte6 "IMM软件版本字节6";
CM_ SG_ 2332156210 I2A_Byrack_Info1_SW_Ver_Byte7 "IMM软件版本字节7";
CM_ SG_ 2332156210 I2A_Byrack_Info1_SW_Ver_Byte8 "IMM软件版本字节8";
CM_ SG_ 2332156211 I2A_Byrack_Info1_SW_Ver_Byte1 "IMM软件版本字节1";
CM_ SG_ 2332156211 I2A_Byrack_Info1_SW_Ver_Byte2 "IMM软件版本字节2";
CM_ SG_ 2332156211 I2A_Byrack_Info1_SW_Ver_Byte3 "IMM软件版本字节3";
CM_ SG_ 2332156211 I2A_Byrack_Info1_SW_Ver_Byte4 "IMM软件版本字节4";
CM_ SG_ 2332156211 I2A_Byrack_Info1_SW_Ver_Byte5 "IMM软件版本字节5";
CM_ SG_ 2332156211 I2A_Byrack_Info1_SW_Ver_Byte6 "IMM软件版本字节6";
CM_ SG_ 2332156211 I2A_Byrack_Info1_SW_Ver_Byte7 "IMM软件版本字节7";
CM_ SG_ 2332156211 I2A_Byrack_Info1_SW_Ver_Byte8 "IMM软件版本字节8";
CM_ SG_ 2332156212 I2A_Byrack_Info1_SW_Ver_Byte1 "IMM软件版本字节1";
CM_ SG_ 2332156212 I2A_Byrack_Info1_SW_Ver_Byte2 "IMM软件版本字节2";
CM_ SG_ 2332156212 I2A_Byrack_Info1_SW_Ver_Byte3 "IMM软件版本字节3";
CM_ SG_ 2332156212 I2A_Byrack_Info1_SW_Ver_Byte4 "IMM软件版本字节4";
CM_ SG_ 2332156212 I2A_Byrack_Info1_SW_Ver_Byte5 "IMM软件版本字节5";
CM_ SG_ 2332156212 I2A_Byrack_Info1_SW_Ver_Byte6 "IMM软件版本字节6";
CM_ SG_ 2332156212 I2A_Byrack_Info1_SW_Ver_Byte7 "IMM软件版本字节7";
CM_ SG_ 2332156212 I2A_Byrack_Info1_SW_Ver_Byte8 "IMM软件版本字节8";
CM_ SG_ 2332156213 I2A_Byrack_Info1_SW_Ver_Byte1 "IMM软件版本字节1";
CM_ SG_ 2332156213 I2A_Byrack_Info1_SW_Ver_Byte2 "IMM软件版本字节2";
CM_ SG_ 2332156213 I2A_Byrack_Info1_SW_Ver_Byte3 "IMM软件版本字节3";
CM_ SG_ 2332156213 I2A_Byrack_Info1_SW_Ver_Byte4 "IMM软件版本字节4";
CM_ SG_ 2332156213 I2A_Byrack_Info1_SW_Ver_Byte5 "IMM软件版本字节5";
CM_ SG_ 2332156213 I2A_Byrack_Info1_SW_Ver_Byte6 "IMM软件版本字节6";
CM_ SG_ 2332156213 I2A_Byrack_Info1_SW_Ver_Byte7 "IMM软件版本字节7";
CM_ SG_ 2332156213 I2A_Byrack_Info1_SW_Ver_Byte8 "IMM软件版本字节8";
CM_ SG_ 2332156214 I2A_Byrack_Info1_SW_Ver_Byte1 "IMM软件版本字节1";
CM_ SG_ 2332156214 I2A_Byrack_Info1_SW_Ver_Byte2 "IMM软件版本字节2";
CM_ SG_ 2332156214 I2A_Byrack_Info1_SW_Ver_Byte3 "IMM软件版本字节3";
CM_ SG_ 2332156214 I2A_Byrack_Info1_SW_Ver_Byte4 "IMM软件版本字节4";
CM_ SG_ 2332156214 I2A_Byrack_Info1_SW_Ver_Byte5 "IMM软件版本字节5";
CM_ SG_ 2332156214 I2A_Byrack_Info1_SW_Ver_Byte6 "IMM软件版本字节6";
CM_ SG_ 2332156214 I2A_Byrack_Info1_SW_Ver_Byte7 "IMM软件版本字节7";
CM_ SG_ 2332156214 I2A_Byrack_Info1_SW_Ver_Byte8 "IMM软件版本字节8";
CM_ SG_ 2332156215 I2A_Byrack_Info1_SW_Ver_Byte1 "IMM软件版本字节1";
CM_ SG_ 2332156215 I2A_Byrack_Info1_SW_Ver_Byte2 "IMM软件版本字节2";
CM_ SG_ 2332156215 I2A_Byrack_Info1_SW_Ver_Byte3 "IMM软件版本字节3";
CM_ SG_ 2332156215 I2A_Byrack_Info1_SW_Ver_Byte4 "IMM软件版本字节4";
CM_ SG_ 2332156215 I2A_Byrack_Info1_SW_Ver_Byte5 "IMM软件版本字节5";
CM_ SG_ 2332156215 I2A_Byrack_Info1_SW_Ver_Byte6 "IMM软件版本字节6";
CM_ SG_ 2332156215 I2A_Byrack_Info1_SW_Ver_Byte7 "IMM软件版本字节7";
CM_ SG_ 2332156215 I2A_Byrack_Info1_SW_Ver_Byte8 "IMM软件版本字节8";
CM_ SG_ 2332156216 I2A_Byrack_Info1_SW_Ver_Byte1 "IMM软件版本字节1";
CM_ SG_ 2332156216 I2A_Byrack_Info1_SW_Ver_Byte2 "IMM软件版本字节2";
CM_ SG_ 2332156216 I2A_Byrack_Info1_SW_Ver_Byte3 "IMM软件版本字节3";
CM_ SG_ 2332156216 I2A_Byrack_Info1_SW_Ver_Byte4 "IMM软件版本字节4";
CM_ SG_ 2332156216 I2A_Byrack_Info1_SW_Ver_Byte5 "IMM软件版本字节5";
CM_ SG_ 2332156216 I2A_Byrack_Info1_SW_Ver_Byte6 "IMM软件版本字节6";
CM_ SG_ 2332156216 I2A_Byrack_Info1_SW_Ver_Byte7 "IMM软件版本字节7";
CM_ SG_ 2332156216 I2A_Byrack_Info1_SW_Ver_Byte8 "IMM软件版本字节8";
CM_ SG_ 2332156217 I2A_Byrack_Info1_SW_Ver_Byte1 "IMM软件版本字节1";
CM_ SG_ 2332156217 I2A_Byrack_Info1_SW_Ver_Byte2 "IMM软件版本字节2";
CM_ SG_ 2332156217 I2A_Byrack_Info1_SW_Ver_Byte3 "IMM软件版本字节3";
CM_ SG_ 2332156217 I2A_Byrack_Info1_SW_Ver_Byte4 "IMM软件版本字节4";
CM_ SG_ 2332156217 I2A_Byrack_Info1_SW_Ver_Byte5 "IMM软件版本字节5";
CM_ SG_ 2332156217 I2A_Byrack_Info1_SW_Ver_Byte6 "IMM软件版本字节6";
CM_ SG_ 2332156217 I2A_Byrack_Info1_SW_Ver_Byte7 "IMM软件版本字节7";
CM_ SG_ 2332156217 I2A_Byrack_Info1_SW_Ver_Byte8 "IMM软件版本字节8";
CM_ SG_ 2332156218 I2A_Byrack_Info1_SW_Ver_Byte1 "IMM软件版本字节1";
CM_ SG_ 2332156218 I2A_Byrack_Info1_SW_Ver_Byte2 "IMM软件版本字节2";
CM_ SG_ 2332156218 I2A_Byrack_Info1_SW_Ver_Byte3 "IMM软件版本字节3";
CM_ SG_ 2332156218 I2A_Byrack_Info1_SW_Ver_Byte4 "IMM软件版本字节4";
CM_ SG_ 2332156218 I2A_Byrack_Info1_SW_Ver_Byte5 "IMM软件版本字节5";
CM_ SG_ 2332156218 I2A_Byrack_Info1_SW_Ver_Byte6 "IMM软件版本字节6";
CM_ SG_ 2332156218 I2A_Byrack_Info1_SW_Ver_Byte7 "IMM软件版本字节7";
CM_ SG_ 2332156218 I2A_Byrack_Info1_SW_Ver_Byte8 "IMM软件版本字节8";
CM_ SG_ 2332156219 I2A_Byrack_Info1_SW_Ver_Byte1 "IMM软件版本字节1";
CM_ SG_ 2332156219 I2A_Byrack_Info1_SW_Ver_Byte2 "IMM软件版本字节2";
CM_ SG_ 2332156219 I2A_Byrack_Info1_SW_Ver_Byte3 "IMM软件版本字节3";
CM_ SG_ 2332156219 I2A_Byrack_Info1_SW_Ver_Byte4 "IMM软件版本字节4";
CM_ SG_ 2332156219 I2A_Byrack_Info1_SW_Ver_Byte5 "IMM软件版本字节5";
CM_ SG_ 2332156219 I2A_Byrack_Info1_SW_Ver_Byte6 "IMM软件版本字节6";
CM_ SG_ 2332156219 I2A_Byrack_Info1_SW_Ver_Byte7 "IMM软件版本字节7";
CM_ SG_ 2332156219 I2A_Byrack_Info1_SW_Ver_Byte8 "IMM软件版本字节8";
CM_ SG_ 2332156220 I2A_Byrack_Info1_SW_Ver_Byte1 "IMM软件版本字节1";
CM_ SG_ 2332156220 I2A_Byrack_Info1_SW_Ver_Byte2 "IMM软件版本字节2";
CM_ SG_ 2332156220 I2A_Byrack_Info1_SW_Ver_Byte3 "IMM软件版本字节3";
CM_ SG_ 2332156220 I2A_Byrack_Info1_SW_Ver_Byte4 "IMM软件版本字节4";
CM_ SG_ 2332156220 I2A_Byrack_Info1_SW_Ver_Byte5 "IMM软件版本字节5";
CM_ SG_ 2332156220 I2A_Byrack_Info1_SW_Ver_Byte6 "IMM软件版本字节6";
CM_ SG_ 2332156220 I2A_Byrack_Info1_SW_Ver_Byte7 "IMM软件版本字节7";
CM_ SG_ 2332156220 I2A_Byrack_Info1_SW_Ver_Byte8 "IMM软件版本字节8";
CM_ SG_ 2332156221 I2A_Byrack_Info1_SW_Ver_Byte1 "IMM软件版本字节1";
CM_ SG_ 2332156221 I2A_Byrack_Info1_SW_Ver_Byte2 "IMM软件版本字节2";
CM_ SG_ 2332156221 I2A_Byrack_Info1_SW_Ver_Byte3 "IMM软件版本字节3";
CM_ SG_ 2332156221 I2A_Byrack_Info1_SW_Ver_Byte4 "IMM软件版本字节4";
CM_ SG_ 2332156221 I2A_Byrack_Info1_SW_Ver_Byte5 "IMM软件版本字节5";
CM_ SG_ 2332156221 I2A_Byrack_Info1_SW_Ver_Byte6 "IMM软件版本字节6";
CM_ SG_ 2332156221 I2A_Byrack_Info1_SW_Ver_Byte7 "IMM软件版本字节7";
CM_ SG_ 2332156221 I2A_Byrack_Info1_SW_Ver_Byte8 "IMM软件版本字节8";
CM_ SG_ 2332156222 I2A_Byrack_Info1_SW_Ver_Byte1 "IMM软件版本字节1";
CM_ SG_ 2332156222 I2A_Byrack_Info1_SW_Ver_Byte2 "IMM软件版本字节2";
CM_ SG_ 2332156222 I2A_Byrack_Info1_SW_Ver_Byte3 "IMM软件版本字节3";
CM_ SG_ 2332156222 I2A_Byrack_Info1_SW_Ver_Byte4 "IMM软件版本字节4";
CM_ SG_ 2332156222 I2A_Byrack_Info1_SW_Ver_Byte5 "IMM软件版本字节5";
CM_ SG_ 2332156222 I2A_Byrack_Info1_SW_Ver_Byte6 "IMM软件版本字节6";
CM_ SG_ 2332156222 I2A_Byrack_Info1_SW_Ver_Byte7 "IMM软件版本字节7";
CM_ SG_ 2332156222 I2A_Byrack_Info1_SW_Ver_Byte8 "IMM软件版本字节8";
CM_ SG_ 2332156223 I2A_Byrack_Info1_SW_Ver_Byte1 "IMM软件版本字节1";
CM_ SG_ 2332156223 I2A_Byrack_Info1_SW_Ver_Byte2 "IMM软件版本字节2";
CM_ SG_ 2332156223 I2A_Byrack_Info1_SW_Ver_Byte3 "IMM软件版本字节3";
CM_ SG_ 2332156223 I2A_Byrack_Info1_SW_Ver_Byte4 "IMM软件版本字节4";
CM_ SG_ 2332156223 I2A_Byrack_Info1_SW_Ver_Byte5 "IMM软件版本字节5";
CM_ SG_ 2332156223 I2A_Byrack_Info1_SW_Ver_Byte6 "IMM软件版本字节6";
CM_ SG_ 2332156223 I2A_Byrack_Info1_SW_Ver_Byte7 "IMM软件版本字节7";
CM_ SG_ 2332156223 I2A_Byrack_Info1_SW_Ver_Byte8 "IMM软件版本字节8";
CM_ SG_ 2332156449 I2A_Byrack_Info2_SW_Ver_Byte9 "IMM软件版本字节9";
CM_ SG_ 2332156449 I2A_Byrack_Info2_SW_Ver_Byte10 "IMM软件版本字节10";
CM_ SG_ 2332156449 I2A_Byrack_Info2_SW_Ver_Byte11 "IMM软件版本字节11";
CM_ SG_ 2332156449 I2A_Byrack_Info2_SW_Ver_Byte12 "IMM软件版本字节12";
CM_ SG_ 2332156449 I2A_Byrack_Info2_SW_Ver_Byte13 "IMM软件版本字节13";
CM_ SG_ 2332156449 I2A_Byrack_Info2_SW_Ver_Byte14 "IMM软件版本字节14";
CM_ SG_ 2332156449 I2A_Byrack_Info2_SW_Ver_Byte15 "IMM软件版本字节15";
CM_ SG_ 2332156449 I2A_Byrack_Info2_SW_Ver_Byte16 "IMM软件版本字节16";
CM_ SG_ 2332156450 I2A_Byrack_Info2_SW_Ver_Byte9 "IMM软件版本字节9";
CM_ SG_ 2332156450 I2A_Byrack_Info2_SW_Ver_Byte10 "IMM软件版本字节10";
CM_ SG_ 2332156450 I2A_Byrack_Info2_SW_Ver_Byte11 "IMM软件版本字节11";
CM_ SG_ 2332156450 I2A_Byrack_Info2_SW_Ver_Byte12 "IMM软件版本字节12";
CM_ SG_ 2332156450 I2A_Byrack_Info2_SW_Ver_Byte13 "IMM软件版本字节13";
CM_ SG_ 2332156450 I2A_Byrack_Info2_SW_Ver_Byte14 "IMM软件版本字节14";
CM_ SG_ 2332156450 I2A_Byrack_Info2_SW_Ver_Byte15 "IMM软件版本字节15";
CM_ SG_ 2332156450 I2A_Byrack_Info2_SW_Ver_Byte16 "IMM软件版本字节16";
CM_ SG_ 2332156451 I2A_Byrack_Info2_SW_Ver_Byte9 "IMM软件版本字节9";
CM_ SG_ 2332156451 I2A_Byrack_Info2_SW_Ver_Byte10 "IMM软件版本字节10";
CM_ SG_ 2332156451 I2A_Byrack_Info2_SW_Ver_Byte11 "IMM软件版本字节11";
CM_ SG_ 2332156451 I2A_Byrack_Info2_SW_Ver_Byte12 "IMM软件版本字节12";
CM_ SG_ 2332156451 I2A_Byrack_Info2_SW_Ver_Byte13 "IMM软件版本字节13";
CM_ SG_ 2332156451 I2A_Byrack_Info2_SW_Ver_Byte14 "IMM软件版本字节14";
CM_ SG_ 2332156451 I2A_Byrack_Info2_SW_Ver_Byte15 "IMM软件版本字节15";
CM_ SG_ 2332156451 I2A_Byrack_Info2_SW_Ver_Byte16 "IMM软件版本字节16";
CM_ SG_ 2332156452 I2A_Byrack_Info2_SW_Ver_Byte9 "IMM软件版本字节9";
CM_ SG_ 2332156452 I2A_Byrack_Info2_SW_Ver_Byte10 "IMM软件版本字节10";
CM_ SG_ 2332156452 I2A_Byrack_Info2_SW_Ver_Byte11 "IMM软件版本字节11";
CM_ SG_ 2332156452 I2A_Byrack_Info2_SW_Ver_Byte12 "IMM软件版本字节12";
CM_ SG_ 2332156452 I2A_Byrack_Info2_SW_Ver_Byte13 "IMM软件版本字节13";
CM_ SG_ 2332156452 I2A_Byrack_Info2_SW_Ver_Byte14 "IMM软件版本字节14";
CM_ SG_ 2332156452 I2A_Byrack_Info2_SW_Ver_Byte15 "IMM软件版本字节15";
CM_ SG_ 2332156452 I2A_Byrack_Info2_SW_Ver_Byte16 "IMM软件版本字节16";
CM_ SG_ 2332156453 I2A_Byrack_Info2_SW_Ver_Byte9 "IMM软件版本字节9";
CM_ SG_ 2332156453 I2A_Byrack_Info2_SW_Ver_Byte10 "IMM软件版本字节10";
CM_ SG_ 2332156453 I2A_Byrack_Info2_SW_Ver_Byte11 "IMM软件版本字节11";
CM_ SG_ 2332156453 I2A_Byrack_Info2_SW_Ver_Byte12 "IMM软件版本字节12";
CM_ SG_ 2332156453 I2A_Byrack_Info2_SW_Ver_Byte13 "IMM软件版本字节13";
CM_ SG_ 2332156453 I2A_Byrack_Info2_SW_Ver_Byte14 "IMM软件版本字节14";
CM_ SG_ 2332156453 I2A_Byrack_Info2_SW_Ver_Byte15 "IMM软件版本字节15";
CM_ SG_ 2332156453 I2A_Byrack_Info2_SW_Ver_Byte16 "IMM软件版本字节16";
CM_ SG_ 2332156454 I2A_Byrack_Info2_SW_Ver_Byte9 "IMM软件版本字节9";
CM_ SG_ 2332156454 I2A_Byrack_Info2_SW_Ver_Byte10 "IMM软件版本字节10";
CM_ SG_ 2332156454 I2A_Byrack_Info2_SW_Ver_Byte11 "IMM软件版本字节11";
CM_ SG_ 2332156454 I2A_Byrack_Info2_SW_Ver_Byte12 "IMM软件版本字节12";
CM_ SG_ 2332156454 I2A_Byrack_Info2_SW_Ver_Byte13 "IMM软件版本字节13";
CM_ SG_ 2332156454 I2A_Byrack_Info2_SW_Ver_Byte14 "IMM软件版本字节14";
CM_ SG_ 2332156454 I2A_Byrack_Info2_SW_Ver_Byte15 "IMM软件版本字节15";
CM_ SG_ 2332156454 I2A_Byrack_Info2_SW_Ver_Byte16 "IMM软件版本字节16";
CM_ SG_ 2332156455 I2A_Byrack_Info2_SW_Ver_Byte9 "IMM软件版本字节9";
CM_ SG_ 2332156455 I2A_Byrack_Info2_SW_Ver_Byte10 "IMM软件版本字节10";
CM_ SG_ 2332156455 I2A_Byrack_Info2_SW_Ver_Byte11 "IMM软件版本字节11";
CM_ SG_ 2332156455 I2A_Byrack_Info2_SW_Ver_Byte12 "IMM软件版本字节12";
CM_ SG_ 2332156455 I2A_Byrack_Info2_SW_Ver_Byte13 "IMM软件版本字节13";
CM_ SG_ 2332156455 I2A_Byrack_Info2_SW_Ver_Byte14 "IMM软件版本字节14";
CM_ SG_ 2332156455 I2A_Byrack_Info2_SW_Ver_Byte15 "IMM软件版本字节15";
CM_ SG_ 2332156455 I2A_Byrack_Info2_SW_Ver_Byte16 "IMM软件版本字节16";
CM_ SG_ 2332156456 I2A_Byrack_Info2_SW_Ver_Byte9 "IMM软件版本字节9";
CM_ SG_ 2332156456 I2A_Byrack_Info2_SW_Ver_Byte10 "IMM软件版本字节10";
CM_ SG_ 2332156456 I2A_Byrack_Info2_SW_Ver_Byte11 "IMM软件版本字节11";
CM_ SG_ 2332156456 I2A_Byrack_Info2_SW_Ver_Byte12 "IMM软件版本字节12";
CM_ SG_ 2332156456 I2A_Byrack_Info2_SW_Ver_Byte13 "IMM软件版本字节13";
CM_ SG_ 2332156456 I2A_Byrack_Info2_SW_Ver_Byte14 "IMM软件版本字节14";
CM_ SG_ 2332156456 I2A_Byrack_Info2_SW_Ver_Byte15 "IMM软件版本字节15";
CM_ SG_ 2332156456 I2A_Byrack_Info2_SW_Ver_Byte16 "IMM软件版本字节16";
CM_ SG_ 2332156457 I2A_Byrack_Info2_SW_Ver_Byte9 "IMM软件版本字节9";
CM_ SG_ 2332156457 I2A_Byrack_Info2_SW_Ver_Byte10 "IMM软件版本字节10";
CM_ SG_ 2332156457 I2A_Byrack_Info2_SW_Ver_Byte11 "IMM软件版本字节11";
CM_ SG_ 2332156457 I2A_Byrack_Info2_SW_Ver_Byte12 "IMM软件版本字节12";
CM_ SG_ 2332156457 I2A_Byrack_Info2_SW_Ver_Byte13 "IMM软件版本字节13";
CM_ SG_ 2332156457 I2A_Byrack_Info2_SW_Ver_Byte14 "IMM软件版本字节14";
CM_ SG_ 2332156457 I2A_Byrack_Info2_SW_Ver_Byte15 "IMM软件版本字节15";
CM_ SG_ 2332156457 I2A_Byrack_Info2_SW_Ver_Byte16 "IMM软件版本字节16";
CM_ SG_ 2332156458 I2A_Byrack_Info2_SW_Ver_Byte9 "IMM软件版本字节9";
CM_ SG_ 2332156458 I2A_Byrack_Info2_SW_Ver_Byte10 "IMM软件版本字节10";
CM_ SG_ 2332156458 I2A_Byrack_Info2_SW_Ver_Byte11 "IMM软件版本字节11";
CM_ SG_ 2332156458 I2A_Byrack_Info2_SW_Ver_Byte12 "IMM软件版本字节12";
CM_ SG_ 2332156458 I2A_Byrack_Info2_SW_Ver_Byte13 "IMM软件版本字节13";
CM_ SG_ 2332156458 I2A_Byrack_Info2_SW_Ver_Byte14 "IMM软件版本字节14";
CM_ SG_ 2332156458 I2A_Byrack_Info2_SW_Ver_Byte15 "IMM软件版本字节15";
CM_ SG_ 2332156458 I2A_Byrack_Info2_SW_Ver_Byte16 "IMM软件版本字节16";
CM_ SG_ 2332156459 I2A_Byrack_Info2_SW_Ver_Byte9 "IMM软件版本字节9";
CM_ SG_ 2332156459 I2A_Byrack_Info2_SW_Ver_Byte10 "IMM软件版本字节10";
CM_ SG_ 2332156459 I2A_Byrack_Info2_SW_Ver_Byte11 "IMM软件版本字节11";
CM_ SG_ 2332156459 I2A_Byrack_Info2_SW_Ver_Byte12 "IMM软件版本字节12";
CM_ SG_ 2332156459 I2A_Byrack_Info2_SW_Ver_Byte13 "IMM软件版本字节13";
CM_ SG_ 2332156459 I2A_Byrack_Info2_SW_Ver_Byte14 "IMM软件版本字节14";
CM_ SG_ 2332156459 I2A_Byrack_Info2_SW_Ver_Byte15 "IMM软件版本字节15";
CM_ SG_ 2332156459 I2A_Byrack_Info2_SW_Ver_Byte16 "IMM软件版本字节16";
CM_ SG_ 2332156460 I2A_Byrack_Info2_SW_Ver_Byte9 "IMM软件版本字节9";
CM_ SG_ 2332156460 I2A_Byrack_Info2_SW_Ver_Byte10 "IMM软件版本字节10";
CM_ SG_ 2332156460 I2A_Byrack_Info2_SW_Ver_Byte11 "IMM软件版本字节11";
CM_ SG_ 2332156460 I2A_Byrack_Info2_SW_Ver_Byte12 "IMM软件版本字节12";
CM_ SG_ 2332156460 I2A_Byrack_Info2_SW_Ver_Byte13 "IMM软件版本字节13";
CM_ SG_ 2332156460 I2A_Byrack_Info2_SW_Ver_Byte14 "IMM软件版本字节14";
CM_ SG_ 2332156460 I2A_Byrack_Info2_SW_Ver_Byte15 "IMM软件版本字节15";
CM_ SG_ 2332156460 I2A_Byrack_Info2_SW_Ver_Byte16 "IMM软件版本字节16";
CM_ SG_ 2332156461 I2A_Byrack_Info2_SW_Ver_Byte9 "IMM软件版本字节9";
CM_ SG_ 2332156461 I2A_Byrack_Info2_SW_Ver_Byte10 "IMM软件版本字节10";
CM_ SG_ 2332156461 I2A_Byrack_Info2_SW_Ver_Byte11 "IMM软件版本字节11";
CM_ SG_ 2332156461 I2A_Byrack_Info2_SW_Ver_Byte12 "IMM软件版本字节12";
CM_ SG_ 2332156461 I2A_Byrack_Info2_SW_Ver_Byte13 "IMM软件版本字节13";
CM_ SG_ 2332156461 I2A_Byrack_Info2_SW_Ver_Byte14 "IMM软件版本字节14";
CM_ SG_ 2332156461 I2A_Byrack_Info2_SW_Ver_Byte15 "IMM软件版本字节15";
CM_ SG_ 2332156461 I2A_Byrack_Info2_SW_Ver_Byte16 "IMM软件版本字节16";
CM_ SG_ 2332156462 I2A_Byrack_Info2_SW_Ver_Byte9 "IMM软件版本字节9";
CM_ SG_ 2332156462 I2A_Byrack_Info2_SW_Ver_Byte10 "IMM软件版本字节10";
CM_ SG_ 2332156462 I2A_Byrack_Info2_SW_Ver_Byte11 "IMM软件版本字节11";
CM_ SG_ 2332156462 I2A_Byrack_Info2_SW_Ver_Byte12 "IMM软件版本字节12";
CM_ SG_ 2332156462 I2A_Byrack_Info2_SW_Ver_Byte13 "IMM软件版本字节13";
CM_ SG_ 2332156462 I2A_Byrack_Info2_SW_Ver_Byte14 "IMM软件版本字节14";
CM_ SG_ 2332156462 I2A_Byrack_Info2_SW_Ver_Byte15 "IMM软件版本字节15";
CM_ SG_ 2332156462 I2A_Byrack_Info2_SW_Ver_Byte16 "IMM软件版本字节16";
CM_ SG_ 2332156463 I2A_Byrack_Info2_SW_Ver_Byte9 "IMM软件版本字节9";
CM_ SG_ 2332156463 I2A_Byrack_Info2_SW_Ver_Byte10 "IMM软件版本字节10";
CM_ SG_ 2332156463 I2A_Byrack_Info2_SW_Ver_Byte11 "IMM软件版本字节11";
CM_ SG_ 2332156463 I2A_Byrack_Info2_SW_Ver_Byte12 "IMM软件版本字节12";
CM_ SG_ 2332156463 I2A_Byrack_Info2_SW_Ver_Byte13 "IMM软件版本字节13";
CM_ SG_ 2332156463 I2A_Byrack_Info2_SW_Ver_Byte14 "IMM软件版本字节14";
CM_ SG_ 2332156463 I2A_Byrack_Info2_SW_Ver_Byte15 "IMM软件版本字节15";
CM_ SG_ 2332156463 I2A_Byrack_Info2_SW_Ver_Byte16 "IMM软件版本字节16";
CM_ SG_ 2332156464 I2A_Byrack_Info2_SW_Ver_Byte9 "IMM软件版本字节9";
CM_ SG_ 2332156464 I2A_Byrack_Info2_SW_Ver_Byte10 "IMM软件版本字节10";
CM_ SG_ 2332156464 I2A_Byrack_Info2_SW_Ver_Byte11 "IMM软件版本字节11";
CM_ SG_ 2332156464 I2A_Byrack_Info2_SW_Ver_Byte12 "IMM软件版本字节12";
CM_ SG_ 2332156464 I2A_Byrack_Info2_SW_Ver_Byte13 "IMM软件版本字节13";
CM_ SG_ 2332156464 I2A_Byrack_Info2_SW_Ver_Byte14 "IMM软件版本字节14";
CM_ SG_ 2332156464 I2A_Byrack_Info2_SW_Ver_Byte15 "IMM软件版本字节15";
CM_ SG_ 2332156464 I2A_Byrack_Info2_SW_Ver_Byte16 "IMM软件版本字节16";
CM_ SG_ 2332156465 I2A_Byrack_Info2_SW_Ver_Byte9 "IMM软件版本字节9";
CM_ SG_ 2332156465 I2A_Byrack_Info2_SW_Ver_Byte10 "IMM软件版本字节10";
CM_ SG_ 2332156465 I2A_Byrack_Info2_SW_Ver_Byte11 "IMM软件版本字节11";
CM_ SG_ 2332156465 I2A_Byrack_Info2_SW_Ver_Byte12 "IMM软件版本字节12";
CM_ SG_ 2332156465 I2A_Byrack_Info2_SW_Ver_Byte13 "IMM软件版本字节13";
CM_ SG_ 2332156465 I2A_Byrack_Info2_SW_Ver_Byte14 "IMM软件版本字节14";
CM_ SG_ 2332156465 I2A_Byrack_Info2_SW_Ver_Byte15 "IMM软件版本字节15";
CM_ SG_ 2332156465 I2A_Byrack_Info2_SW_Ver_Byte16 "IMM软件版本字节16";
CM_ SG_ 2332156466 I2A_Byrack_Info2_SW_Ver_Byte9 "IMM软件版本字节9";
CM_ SG_ 2332156466 I2A_Byrack_Info2_SW_Ver_Byte10 "IMM软件版本字节10";
CM_ SG_ 2332156466 I2A_Byrack_Info2_SW_Ver_Byte11 "IMM软件版本字节11";
CM_ SG_ 2332156466 I2A_Byrack_Info2_SW_Ver_Byte12 "IMM软件版本字节12";
CM_ SG_ 2332156466 I2A_Byrack_Info2_SW_Ver_Byte13 "IMM软件版本字节13";
CM_ SG_ 2332156466 I2A_Byrack_Info2_SW_Ver_Byte14 "IMM软件版本字节14";
CM_ SG_ 2332156466 I2A_Byrack_Info2_SW_Ver_Byte15 "IMM软件版本字节15";
CM_ SG_ 2332156466 I2A_Byrack_Info2_SW_Ver_Byte16 "IMM软件版本字节16";
CM_ SG_ 2332156467 I2A_Byrack_Info2_SW_Ver_Byte9 "IMM软件版本字节9";
CM_ SG_ 2332156467 I2A_Byrack_Info2_SW_Ver_Byte10 "IMM软件版本字节10";
CM_ SG_ 2332156467 I2A_Byrack_Info2_SW_Ver_Byte11 "IMM软件版本字节11";
CM_ SG_ 2332156467 I2A_Byrack_Info2_SW_Ver_Byte12 "IMM软件版本字节12";
CM_ SG_ 2332156467 I2A_Byrack_Info2_SW_Ver_Byte13 "IMM软件版本字节13";
CM_ SG_ 2332156467 I2A_Byrack_Info2_SW_Ver_Byte14 "IMM软件版本字节14";
CM_ SG_ 2332156467 I2A_Byrack_Info2_SW_Ver_Byte15 "IMM软件版本字节15";
CM_ SG_ 2332156467 I2A_Byrack_Info2_SW_Ver_Byte16 "IMM软件版本字节16";
CM_ SG_ 2332156468 I2A_Byrack_Info2_SW_Ver_Byte9 "IMM软件版本字节9";
CM_ SG_ 2332156468 I2A_Byrack_Info2_SW_Ver_Byte10 "IMM软件版本字节10";
CM_ SG_ 2332156468 I2A_Byrack_Info2_SW_Ver_Byte11 "IMM软件版本字节11";
CM_ SG_ 2332156468 I2A_Byrack_Info2_SW_Ver_Byte12 "IMM软件版本字节12";
CM_ SG_ 2332156468 I2A_Byrack_Info2_SW_Ver_Byte13 "IMM软件版本字节13";
CM_ SG_ 2332156468 I2A_Byrack_Info2_SW_Ver_Byte14 "IMM软件版本字节14";
CM_ SG_ 2332156468 I2A_Byrack_Info2_SW_Ver_Byte15 "IMM软件版本字节15";
CM_ SG_ 2332156468 I2A_Byrack_Info2_SW_Ver_Byte16 "IMM软件版本字节16";
CM_ SG_ 2332156469 I2A_Byrack_Info2_SW_Ver_Byte9 "IMM软件版本字节9";
CM_ SG_ 2332156469 I2A_Byrack_Info2_SW_Ver_Byte10 "IMM软件版本字节10";
CM_ SG_ 2332156469 I2A_Byrack_Info2_SW_Ver_Byte11 "IMM软件版本字节11";
CM_ SG_ 2332156469 I2A_Byrack_Info2_SW_Ver_Byte12 "IMM软件版本字节12";
CM_ SG_ 2332156469 I2A_Byrack_Info2_SW_Ver_Byte13 "IMM软件版本字节13";
CM_ SG_ 2332156469 I2A_Byrack_Info2_SW_Ver_Byte14 "IMM软件版本字节14";
CM_ SG_ 2332156469 I2A_Byrack_Info2_SW_Ver_Byte15 "IMM软件版本字节15";
CM_ SG_ 2332156469 I2A_Byrack_Info2_SW_Ver_Byte16 "IMM软件版本字节16";
CM_ SG_ 2332156470 I2A_Byrack_Info2_SW_Ver_Byte9 "IMM软件版本字节9";
CM_ SG_ 2332156470 I2A_Byrack_Info2_SW_Ver_Byte10 "IMM软件版本字节10";
CM_ SG_ 2332156470 I2A_Byrack_Info2_SW_Ver_Byte11 "IMM软件版本字节11";
CM_ SG_ 2332156470 I2A_Byrack_Info2_SW_Ver_Byte12 "IMM软件版本字节12";
CM_ SG_ 2332156470 I2A_Byrack_Info2_SW_Ver_Byte13 "IMM软件版本字节13";
CM_ SG_ 2332156470 I2A_Byrack_Info2_SW_Ver_Byte14 "IMM软件版本字节14";
CM_ SG_ 2332156470 I2A_Byrack_Info2_SW_Ver_Byte15 "IMM软件版本字节15";
CM_ SG_ 2332156470 I2A_Byrack_Info2_SW_Ver_Byte16 "IMM软件版本字节16";
CM_ SG_ 2332156471 I2A_Byrack_Info2_SW_Ver_Byte9 "IMM软件版本字节9";
CM_ SG_ 2332156471 I2A_Byrack_Info2_SW_Ver_Byte10 "IMM软件版本字节10";
CM_ SG_ 2332156471 I2A_Byrack_Info2_SW_Ver_Byte11 "IMM软件版本字节11";
CM_ SG_ 2332156471 I2A_Byrack_Info2_SW_Ver_Byte12 "IMM软件版本字节12";
CM_ SG_ 2332156471 I2A_Byrack_Info2_SW_Ver_Byte13 "IMM软件版本字节13";
CM_ SG_ 2332156471 I2A_Byrack_Info2_SW_Ver_Byte14 "IMM软件版本字节14";
CM_ SG_ 2332156471 I2A_Byrack_Info2_SW_Ver_Byte15 "IMM软件版本字节15";
CM_ SG_ 2332156471 I2A_Byrack_Info2_SW_Ver_Byte16 "IMM软件版本字节16";
CM_ SG_ 2332156472 I2A_Byrack_Info2_SW_Ver_Byte9 "IMM软件版本字节9";
CM_ SG_ 2332156472 I2A_Byrack_Info2_SW_Ver_Byte10 "IMM软件版本字节10";
CM_ SG_ 2332156472 I2A_Byrack_Info2_SW_Ver_Byte11 "IMM软件版本字节11";
CM_ SG_ 2332156472 I2A_Byrack_Info2_SW_Ver_Byte12 "IMM软件版本字节12";
CM_ SG_ 2332156472 I2A_Byrack_Info2_SW_Ver_Byte13 "IMM软件版本字节13";
CM_ SG_ 2332156472 I2A_Byrack_Info2_SW_Ver_Byte14 "IMM软件版本字节14";
CM_ SG_ 2332156472 I2A_Byrack_Info2_SW_Ver_Byte15 "IMM软件版本字节15";
CM_ SG_ 2332156472 I2A_Byrack_Info2_SW_Ver_Byte16 "IMM软件版本字节16";
CM_ SG_ 2332156473 I2A_Byrack_Info2_SW_Ver_Byte9 "IMM软件版本字节9";
CM_ SG_ 2332156473 I2A_Byrack_Info2_SW_Ver_Byte10 "IMM软件版本字节10";
CM_ SG_ 2332156473 I2A_Byrack_Info2_SW_Ver_Byte11 "IMM软件版本字节11";
CM_ SG_ 2332156473 I2A_Byrack_Info2_SW_Ver_Byte12 "IMM软件版本字节12";
CM_ SG_ 2332156473 I2A_Byrack_Info2_SW_Ver_Byte13 "IMM软件版本字节13";
CM_ SG_ 2332156473 I2A_Byrack_Info2_SW_Ver_Byte14 "IMM软件版本字节14";
CM_ SG_ 2332156473 I2A_Byrack_Info2_SW_Ver_Byte15 "IMM软件版本字节15";
CM_ SG_ 2332156473 I2A_Byrack_Info2_SW_Ver_Byte16 "IMM软件版本字节16";
CM_ SG_ 2332156474 I2A_Byrack_Info2_SW_Ver_Byte9 "IMM软件版本字节9";
CM_ SG_ 2332156474 I2A_Byrack_Info2_SW_Ver_Byte10 "IMM软件版本字节10";
CM_ SG_ 2332156474 I2A_Byrack_Info2_SW_Ver_Byte11 "IMM软件版本字节11";
CM_ SG_ 2332156474 I2A_Byrack_Info2_SW_Ver_Byte12 "IMM软件版本字节12";
CM_ SG_ 2332156474 I2A_Byrack_Info2_SW_Ver_Byte13 "IMM软件版本字节13";
CM_ SG_ 2332156474 I2A_Byrack_Info2_SW_Ver_Byte14 "IMM软件版本字节14";
CM_ SG_ 2332156474 I2A_Byrack_Info2_SW_Ver_Byte15 "IMM软件版本字节15";
CM_ SG_ 2332156474 I2A_Byrack_Info2_SW_Ver_Byte16 "IMM软件版本字节16";
CM_ SG_ 2332156475 I2A_Byrack_Info2_SW_Ver_Byte9 "IMM软件版本字节9";
CM_ SG_ 2332156475 I2A_Byrack_Info2_SW_Ver_Byte10 "IMM软件版本字节10";
CM_ SG_ 2332156475 I2A_Byrack_Info2_SW_Ver_Byte11 "IMM软件版本字节11";
CM_ SG_ 2332156475 I2A_Byrack_Info2_SW_Ver_Byte12 "IMM软件版本字节12";
CM_ SG_ 2332156475 I2A_Byrack_Info2_SW_Ver_Byte13 "IMM软件版本字节13";
CM_ SG_ 2332156475 I2A_Byrack_Info2_SW_Ver_Byte14 "IMM软件版本字节14";
CM_ SG_ 2332156475 I2A_Byrack_Info2_SW_Ver_Byte15 "IMM软件版本字节15";
CM_ SG_ 2332156475 I2A_Byrack_Info2_SW_Ver_Byte16 "IMM软件版本字节16";
CM_ SG_ 2332156476 I2A_Byrack_Info2_SW_Ver_Byte9 "IMM软件版本字节9";
CM_ SG_ 2332156476 I2A_Byrack_Info2_SW_Ver_Byte10 "IMM软件版本字节10";
CM_ SG_ 2332156476 I2A_Byrack_Info2_SW_Ver_Byte11 "IMM软件版本字节11";
CM_ SG_ 2332156476 I2A_Byrack_Info2_SW_Ver_Byte12 "IMM软件版本字节12";
CM_ SG_ 2332156476 I2A_Byrack_Info2_SW_Ver_Byte13 "IMM软件版本字节13";
CM_ SG_ 2332156476 I2A_Byrack_Info2_SW_Ver_Byte14 "IMM软件版本字节14";
CM_ SG_ 2332156476 I2A_Byrack_Info2_SW_Ver_Byte15 "IMM软件版本字节15";
CM_ SG_ 2332156476 I2A_Byrack_Info2_SW_Ver_Byte16 "IMM软件版本字节16";
CM_ SG_ 2332156477 I2A_Byrack_Info2_SW_Ver_Byte9 "IMM软件版本字节9";
CM_ SG_ 2332156477 I2A_Byrack_Info2_SW_Ver_Byte10 "IMM软件版本字节10";
CM_ SG_ 2332156477 I2A_Byrack_Info2_SW_Ver_Byte11 "IMM软件版本字节11";
CM_ SG_ 2332156477 I2A_Byrack_Info2_SW_Ver_Byte12 "IMM软件版本字节12";
CM_ SG_ 2332156477 I2A_Byrack_Info2_SW_Ver_Byte13 "IMM软件版本字节13";
CM_ SG_ 2332156477 I2A_Byrack_Info2_SW_Ver_Byte14 "IMM软件版本字节14";
CM_ SG_ 2332156477 I2A_Byrack_Info2_SW_Ver_Byte15 "IMM软件版本字节15";
CM_ SG_ 2332156477 I2A_Byrack_Info2_SW_Ver_Byte16 "IMM软件版本字节16";
CM_ SG_ 2332156478 I2A_Byrack_Info2_SW_Ver_Byte9 "IMM软件版本字节9";
CM_ SG_ 2332156478 I2A_Byrack_Info2_SW_Ver_Byte10 "IMM软件版本字节10";
CM_ SG_ 2332156478 I2A_Byrack_Info2_SW_Ver_Byte11 "IMM软件版本字节11";
CM_ SG_ 2332156478 I2A_Byrack_Info2_SW_Ver_Byte12 "IMM软件版本字节12";
CM_ SG_ 2332156478 I2A_Byrack_Info2_SW_Ver_Byte13 "IMM软件版本字节13";
CM_ SG_ 2332156478 I2A_Byrack_Info2_SW_Ver_Byte14 "IMM软件版本字节14";
CM_ SG_ 2332156478 I2A_Byrack_Info2_SW_Ver_Byte15 "IMM软件版本字节15";
CM_ SG_ 2332156478 I2A_Byrack_Info2_SW_Ver_Byte16 "IMM软件版本字节16";
CM_ SG_ 2332156479 I2A_Byrack_Info2_SW_Ver_Byte9 "IMM软件版本字节9";
CM_ SG_ 2332156479 I2A_Byrack_Info2_SW_Ver_Byte10 "IMM软件版本字节10";
CM_ SG_ 2332156479 I2A_Byrack_Info2_SW_Ver_Byte11 "IMM软件版本字节11";
CM_ SG_ 2332156479 I2A_Byrack_Info2_SW_Ver_Byte12 "IMM软件版本字节12";
CM_ SG_ 2332156479 I2A_Byrack_Info2_SW_Ver_Byte13 "IMM软件版本字节13";
CM_ SG_ 2332156479 I2A_Byrack_Info2_SW_Ver_Byte14 "IMM软件版本字节14";
CM_ SG_ 2332156479 I2A_Byrack_Info2_SW_Ver_Byte15 "IMM软件版本字节15";
CM_ SG_ 2332156479 I2A_Byrack_Info2_SW_Ver_Byte16 "IMM软件版本字节16";
CM_ SG_ 2332156705 I2A_Byrack_Info3_HW_Ver_Byte1 "IMM硬件版本字节1";
CM_ SG_ 2332156705 I2A_Byrack_Info3_HW_Ver_Byte2 "IMM硬件版本字节2";
CM_ SG_ 2332156705 I2A_Byrack_Info3_HW_Ver_Byte3 "IMM硬件版本字节3";
CM_ SG_ 2332156705 I2A_Byrack_Info3_HW_Ver_Byte4 "IMM硬件版本字节4";
CM_ SG_ 2332156705 I2A_Byrack_Info3_HW_Ver_Byte5 "IMM硬件版本字节5";
CM_ SG_ 2332156705 I2A_Byrack_Info3_HW_Ver_Byte6 "IMM硬件版本字节6";
CM_ SG_ 2332156705 I2A_Byrack_Info3_HW_Ver_Byte7 "IMM硬件版本字节7";
CM_ SG_ 2332156705 I2A_Byrack_Info3_HW_Ver_Byte8 "IMM硬件版本字节8";
CM_ SG_ 2332156706 I2A_Byrack_Info3_HW_Ver_Byte1 "IMM硬件版本字节1";
CM_ SG_ 2332156706 I2A_Byrack_Info3_HW_Ver_Byte2 "IMM硬件版本字节2";
CM_ SG_ 2332156706 I2A_Byrack_Info3_HW_Ver_Byte3 "IMM硬件版本字节3";
CM_ SG_ 2332156706 I2A_Byrack_Info3_HW_Ver_Byte4 "IMM硬件版本字节4";
CM_ SG_ 2332156706 I2A_Byrack_Info3_HW_Ver_Byte5 "IMM硬件版本字节5";
CM_ SG_ 2332156706 I2A_Byrack_Info3_HW_Ver_Byte6 "IMM硬件版本字节6";
CM_ SG_ 2332156706 I2A_Byrack_Info3_HW_Ver_Byte7 "IMM硬件版本字节7";
CM_ SG_ 2332156706 I2A_Byrack_Info3_HW_Ver_Byte8 "IMM硬件版本字节8";
CM_ SG_ 2332156707 I2A_Byrack_Info3_HW_Ver_Byte1 "IMM硬件版本字节1";
CM_ SG_ 2332156707 I2A_Byrack_Info3_HW_Ver_Byte2 "IMM硬件版本字节2";
CM_ SG_ 2332156707 I2A_Byrack_Info3_HW_Ver_Byte3 "IMM硬件版本字节3";
CM_ SG_ 2332156707 I2A_Byrack_Info3_HW_Ver_Byte4 "IMM硬件版本字节4";
CM_ SG_ 2332156707 I2A_Byrack_Info3_HW_Ver_Byte5 "IMM硬件版本字节5";
CM_ SG_ 2332156707 I2A_Byrack_Info3_HW_Ver_Byte6 "IMM硬件版本字节6";
CM_ SG_ 2332156707 I2A_Byrack_Info3_HW_Ver_Byte7 "IMM硬件版本字节7";
CM_ SG_ 2332156707 I2A_Byrack_Info3_HW_Ver_Byte8 "IMM硬件版本字节8";
CM_ SG_ 2332156708 I2A_Byrack_Info3_HW_Ver_Byte1 "IMM硬件版本字节1";
CM_ SG_ 2332156708 I2A_Byrack_Info3_HW_Ver_Byte2 "IMM硬件版本字节2";
CM_ SG_ 2332156708 I2A_Byrack_Info3_HW_Ver_Byte3 "IMM硬件版本字节3";
CM_ SG_ 2332156708 I2A_Byrack_Info3_HW_Ver_Byte4 "IMM硬件版本字节4";
CM_ SG_ 2332156708 I2A_Byrack_Info3_HW_Ver_Byte5 "IMM硬件版本字节5";
CM_ SG_ 2332156708 I2A_Byrack_Info3_HW_Ver_Byte6 "IMM硬件版本字节6";
CM_ SG_ 2332156708 I2A_Byrack_Info3_HW_Ver_Byte7 "IMM硬件版本字节7";
CM_ SG_ 2332156708 I2A_Byrack_Info3_HW_Ver_Byte8 "IMM硬件版本字节8";
CM_ SG_ 2332156709 I2A_Byrack_Info3_HW_Ver_Byte1 "IMM硬件版本字节1";
CM_ SG_ 2332156709 I2A_Byrack_Info3_HW_Ver_Byte2 "IMM硬件版本字节2";
CM_ SG_ 2332156709 I2A_Byrack_Info3_HW_Ver_Byte3 "IMM硬件版本字节3";
CM_ SG_ 2332156709 I2A_Byrack_Info3_HW_Ver_Byte4 "IMM硬件版本字节4";
CM_ SG_ 2332156709 I2A_Byrack_Info3_HW_Ver_Byte5 "IMM硬件版本字节5";
CM_ SG_ 2332156709 I2A_Byrack_Info3_HW_Ver_Byte6 "IMM硬件版本字节6";
CM_ SG_ 2332156709 I2A_Byrack_Info3_HW_Ver_Byte7 "IMM硬件版本字节7";
CM_ SG_ 2332156709 I2A_Byrack_Info3_HW_Ver_Byte8 "IMM硬件版本字节8";
CM_ SG_ 2332156710 I2A_Byrack_Info3_HW_Ver_Byte1 "IMM硬件版本字节1";
CM_ SG_ 2332156710 I2A_Byrack_Info3_HW_Ver_Byte2 "IMM硬件版本字节2";
CM_ SG_ 2332156710 I2A_Byrack_Info3_HW_Ver_Byte3 "IMM硬件版本字节3";
CM_ SG_ 2332156710 I2A_Byrack_Info3_HW_Ver_Byte4 "IMM硬件版本字节4";
CM_ SG_ 2332156710 I2A_Byrack_Info3_HW_Ver_Byte5 "IMM硬件版本字节5";
CM_ SG_ 2332156710 I2A_Byrack_Info3_HW_Ver_Byte6 "IMM硬件版本字节6";
CM_ SG_ 2332156710 I2A_Byrack_Info3_HW_Ver_Byte7 "IMM硬件版本字节7";
CM_ SG_ 2332156710 I2A_Byrack_Info3_HW_Ver_Byte8 "IMM硬件版本字节8";
CM_ SG_ 2332156711 I2A_Byrack_Info3_HW_Ver_Byte1 "IMM硬件版本字节1";
CM_ SG_ 2332156711 I2A_Byrack_Info3_HW_Ver_Byte2 "IMM硬件版本字节2";
CM_ SG_ 2332156711 I2A_Byrack_Info3_HW_Ver_Byte3 "IMM硬件版本字节3";
CM_ SG_ 2332156711 I2A_Byrack_Info3_HW_Ver_Byte4 "IMM硬件版本字节4";
CM_ SG_ 2332156711 I2A_Byrack_Info3_HW_Ver_Byte5 "IMM硬件版本字节5";
CM_ SG_ 2332156711 I2A_Byrack_Info3_HW_Ver_Byte6 "IMM硬件版本字节6";
CM_ SG_ 2332156711 I2A_Byrack_Info3_HW_Ver_Byte7 "IMM硬件版本字节7";
CM_ SG_ 2332156711 I2A_Byrack_Info3_HW_Ver_Byte8 "IMM硬件版本字节8";
CM_ SG_ 2332156712 I2A_Byrack_Info3_HW_Ver_Byte1 "IMM硬件版本字节1";
CM_ SG_ 2332156712 I2A_Byrack_Info3_HW_Ver_Byte2 "IMM硬件版本字节2";
CM_ SG_ 2332156712 I2A_Byrack_Info3_HW_Ver_Byte3 "IMM硬件版本字节3";
CM_ SG_ 2332156712 I2A_Byrack_Info3_HW_Ver_Byte4 "IMM硬件版本字节4";
CM_ SG_ 2332156712 I2A_Byrack_Info3_HW_Ver_Byte5 "IMM硬件版本字节5";
CM_ SG_ 2332156712 I2A_Byrack_Info3_HW_Ver_Byte6 "IMM硬件版本字节6";
CM_ SG_ 2332156712 I2A_Byrack_Info3_HW_Ver_Byte7 "IMM硬件版本字节7";
CM_ SG_ 2332156712 I2A_Byrack_Info3_HW_Ver_Byte8 "IMM硬件版本字节8";
CM_ SG_ 2332156713 I2A_Byrack_Info3_HW_Ver_Byte1 "IMM硬件版本字节1";
CM_ SG_ 2332156713 I2A_Byrack_Info3_HW_Ver_Byte2 "IMM硬件版本字节2";
CM_ SG_ 2332156713 I2A_Byrack_Info3_HW_Ver_Byte3 "IMM硬件版本字节3";
CM_ SG_ 2332156713 I2A_Byrack_Info3_HW_Ver_Byte4 "IMM硬件版本字节4";
CM_ SG_ 2332156713 I2A_Byrack_Info3_HW_Ver_Byte5 "IMM硬件版本字节5";
CM_ SG_ 2332156713 I2A_Byrack_Info3_HW_Ver_Byte6 "IMM硬件版本字节6";
CM_ SG_ 2332156713 I2A_Byrack_Info3_HW_Ver_Byte7 "IMM硬件版本字节7";
CM_ SG_ 2332156713 I2A_Byrack_Info3_HW_Ver_Byte8 "IMM硬件版本字节8";
CM_ SG_ 2332156714 I2A_Byrack_Info3_HW_Ver_Byte1 "IMM硬件版本字节1";
CM_ SG_ 2332156714 I2A_Byrack_Info3_HW_Ver_Byte2 "IMM硬件版本字节2";
CM_ SG_ 2332156714 I2A_Byrack_Info3_HW_Ver_Byte3 "IMM硬件版本字节3";
CM_ SG_ 2332156714 I2A_Byrack_Info3_HW_Ver_Byte4 "IMM硬件版本字节4";
CM_ SG_ 2332156714 I2A_Byrack_Info3_HW_Ver_Byte5 "IMM硬件版本字节5";
CM_ SG_ 2332156714 I2A_Byrack_Info3_HW_Ver_Byte6 "IMM硬件版本字节6";
CM_ SG_ 2332156714 I2A_Byrack_Info3_HW_Ver_Byte7 "IMM硬件版本字节7";
CM_ SG_ 2332156714 I2A_Byrack_Info3_HW_Ver_Byte8 "IMM硬件版本字节8";
CM_ SG_ 2332156715 I2A_Byrack_Info3_HW_Ver_Byte1 "IMM硬件版本字节1";
CM_ SG_ 2332156715 I2A_Byrack_Info3_HW_Ver_Byte2 "IMM硬件版本字节2";
CM_ SG_ 2332156715 I2A_Byrack_Info3_HW_Ver_Byte3 "IMM硬件版本字节3";
CM_ SG_ 2332156715 I2A_Byrack_Info3_HW_Ver_Byte4 "IMM硬件版本字节4";
CM_ SG_ 2332156715 I2A_Byrack_Info3_HW_Ver_Byte5 "IMM硬件版本字节5";
CM_ SG_ 2332156715 I2A_Byrack_Info3_HW_Ver_Byte6 "IMM硬件版本字节6";
CM_ SG_ 2332156715 I2A_Byrack_Info3_HW_Ver_Byte7 "IMM硬件版本字节7";
CM_ SG_ 2332156715 I2A_Byrack_Info3_HW_Ver_Byte8 "IMM硬件版本字节8";
CM_ SG_ 2332156716 I2A_Byrack_Info3_HW_Ver_Byte1 "IMM硬件版本字节1";
CM_ SG_ 2332156716 I2A_Byrack_Info3_HW_Ver_Byte2 "IMM硬件版本字节2";
CM_ SG_ 2332156716 I2A_Byrack_Info3_HW_Ver_Byte3 "IMM硬件版本字节3";
CM_ SG_ 2332156716 I2A_Byrack_Info3_HW_Ver_Byte4 "IMM硬件版本字节4";
CM_ SG_ 2332156716 I2A_Byrack_Info3_HW_Ver_Byte5 "IMM硬件版本字节5";
CM_ SG_ 2332156716 I2A_Byrack_Info3_HW_Ver_Byte6 "IMM硬件版本字节6";
CM_ SG_ 2332156716 I2A_Byrack_Info3_HW_Ver_Byte7 "IMM硬件版本字节7";
CM_ SG_ 2332156716 I2A_Byrack_Info3_HW_Ver_Byte8 "IMM硬件版本字节8";
CM_ SG_ 2332156717 I2A_Byrack_Info3_HW_Ver_Byte1 "IMM硬件版本字节1";
CM_ SG_ 2332156717 I2A_Byrack_Info3_HW_Ver_Byte2 "IMM硬件版本字节2";
CM_ SG_ 2332156717 I2A_Byrack_Info3_HW_Ver_Byte3 "IMM硬件版本字节3";
CM_ SG_ 2332156717 I2A_Byrack_Info3_HW_Ver_Byte4 "IMM硬件版本字节4";
CM_ SG_ 2332156717 I2A_Byrack_Info3_HW_Ver_Byte5 "IMM硬件版本字节5";
CM_ SG_ 2332156717 I2A_Byrack_Info3_HW_Ver_Byte6 "IMM硬件版本字节6";
CM_ SG_ 2332156717 I2A_Byrack_Info3_HW_Ver_Byte7 "IMM硬件版本字节7";
CM_ SG_ 2332156717 I2A_Byrack_Info3_HW_Ver_Byte8 "IMM硬件版本字节8";
CM_ SG_ 2332156718 I2A_Byrack_Info3_HW_Ver_Byte1 "IMM硬件版本字节1";
CM_ SG_ 2332156718 I2A_Byrack_Info3_HW_Ver_Byte2 "IMM硬件版本字节2";
CM_ SG_ 2332156718 I2A_Byrack_Info3_HW_Ver_Byte3 "IMM硬件版本字节3";
CM_ SG_ 2332156718 I2A_Byrack_Info3_HW_Ver_Byte4 "IMM硬件版本字节4";
CM_ SG_ 2332156718 I2A_Byrack_Info3_HW_Ver_Byte5 "IMM硬件版本字节5";
CM_ SG_ 2332156718 I2A_Byrack_Info3_HW_Ver_Byte6 "IMM硬件版本字节6";
CM_ SG_ 2332156718 I2A_Byrack_Info3_HW_Ver_Byte7 "IMM硬件版本字节7";
CM_ SG_ 2332156718 I2A_Byrack_Info3_HW_Ver_Byte8 "IMM硬件版本字节8";
CM_ SG_ 2332156719 I2A_Byrack_Info3_HW_Ver_Byte1 "IMM硬件版本字节1";
CM_ SG_ 2332156719 I2A_Byrack_Info3_HW_Ver_Byte2 "IMM硬件版本字节2";
CM_ SG_ 2332156719 I2A_Byrack_Info3_HW_Ver_Byte3 "IMM硬件版本字节3";
CM_ SG_ 2332156719 I2A_Byrack_Info3_HW_Ver_Byte4 "IMM硬件版本字节4";
CM_ SG_ 2332156719 I2A_Byrack_Info3_HW_Ver_Byte5 "IMM硬件版本字节5";
CM_ SG_ 2332156719 I2A_Byrack_Info3_HW_Ver_Byte6 "IMM硬件版本字节6";
CM_ SG_ 2332156719 I2A_Byrack_Info3_HW_Ver_Byte7 "IMM硬件版本字节7";
CM_ SG_ 2332156719 I2A_Byrack_Info3_HW_Ver_Byte8 "IMM硬件版本字节8";
CM_ SG_ 2332156720 I2A_Byrack_Info3_HW_Ver_Byte1 "IMM硬件版本字节1";
CM_ SG_ 2332156720 I2A_Byrack_Info3_HW_Ver_Byte2 "IMM硬件版本字节2";
CM_ SG_ 2332156720 I2A_Byrack_Info3_HW_Ver_Byte3 "IMM硬件版本字节3";
CM_ SG_ 2332156720 I2A_Byrack_Info3_HW_Ver_Byte4 "IMM硬件版本字节4";
CM_ SG_ 2332156720 I2A_Byrack_Info3_HW_Ver_Byte5 "IMM硬件版本字节5";
CM_ SG_ 2332156720 I2A_Byrack_Info3_HW_Ver_Byte6 "IMM硬件版本字节6";
CM_ SG_ 2332156720 I2A_Byrack_Info3_HW_Ver_Byte7 "IMM硬件版本字节7";
CM_ SG_ 2332156720 I2A_Byrack_Info3_HW_Ver_Byte8 "IMM硬件版本字节8";
CM_ SG_ 2332156721 I2A_Byrack_Info3_HW_Ver_Byte1 "IMM硬件版本字节1";
CM_ SG_ 2332156721 I2A_Byrack_Info3_HW_Ver_Byte2 "IMM硬件版本字节2";
CM_ SG_ 2332156721 I2A_Byrack_Info3_HW_Ver_Byte3 "IMM硬件版本字节3";
CM_ SG_ 2332156721 I2A_Byrack_Info3_HW_Ver_Byte4 "IMM硬件版本字节4";
CM_ SG_ 2332156721 I2A_Byrack_Info3_HW_Ver_Byte5 "IMM硬件版本字节5";
CM_ SG_ 2332156721 I2A_Byrack_Info3_HW_Ver_Byte6 "IMM硬件版本字节6";
CM_ SG_ 2332156721 I2A_Byrack_Info3_HW_Ver_Byte7 "IMM硬件版本字节7";
CM_ SG_ 2332156721 I2A_Byrack_Info3_HW_Ver_Byte8 "IMM硬件版本字节8";
CM_ SG_ 2332156722 I2A_Byrack_Info3_HW_Ver_Byte1 "IMM硬件版本字节1";
CM_ SG_ 2332156722 I2A_Byrack_Info3_HW_Ver_Byte2 "IMM硬件版本字节2";
CM_ SG_ 2332156722 I2A_Byrack_Info3_HW_Ver_Byte3 "IMM硬件版本字节3";
CM_ SG_ 2332156722 I2A_Byrack_Info3_HW_Ver_Byte4 "IMM硬件版本字节4";
CM_ SG_ 2332156722 I2A_Byrack_Info3_HW_Ver_Byte5 "IMM硬件版本字节5";
CM_ SG_ 2332156722 I2A_Byrack_Info3_HW_Ver_Byte6 "IMM硬件版本字节6";
CM_ SG_ 2332156722 I2A_Byrack_Info3_HW_Ver_Byte7 "IMM硬件版本字节7";
CM_ SG_ 2332156722 I2A_Byrack_Info3_HW_Ver_Byte8 "IMM硬件版本字节8";
CM_ SG_ 2332156723 I2A_Byrack_Info3_HW_Ver_Byte1 "IMM硬件版本字节1";
CM_ SG_ 2332156723 I2A_Byrack_Info3_HW_Ver_Byte2 "IMM硬件版本字节2";
CM_ SG_ 2332156723 I2A_Byrack_Info3_HW_Ver_Byte3 "IMM硬件版本字节3";
CM_ SG_ 2332156723 I2A_Byrack_Info3_HW_Ver_Byte4 "IMM硬件版本字节4";
CM_ SG_ 2332156723 I2A_Byrack_Info3_HW_Ver_Byte5 "IMM硬件版本字节5";
CM_ SG_ 2332156723 I2A_Byrack_Info3_HW_Ver_Byte6 "IMM硬件版本字节6";
CM_ SG_ 2332156723 I2A_Byrack_Info3_HW_Ver_Byte7 "IMM硬件版本字节7";
CM_ SG_ 2332156723 I2A_Byrack_Info3_HW_Ver_Byte8 "IMM硬件版本字节8";
CM_ SG_ 2332156724 I2A_Byrack_Info3_HW_Ver_Byte1 "IMM硬件版本字节1";
CM_ SG_ 2332156724 I2A_Byrack_Info3_HW_Ver_Byte2 "IMM硬件版本字节2";
CM_ SG_ 2332156724 I2A_Byrack_Info3_HW_Ver_Byte3 "IMM硬件版本字节3";
CM_ SG_ 2332156724 I2A_Byrack_Info3_HW_Ver_Byte4 "IMM硬件版本字节4";
CM_ SG_ 2332156724 I2A_Byrack_Info3_HW_Ver_Byte5 "IMM硬件版本字节5";
CM_ SG_ 2332156724 I2A_Byrack_Info3_HW_Ver_Byte6 "IMM硬件版本字节6";
CM_ SG_ 2332156724 I2A_Byrack_Info3_HW_Ver_Byte7 "IMM硬件版本字节7";
CM_ SG_ 2332156724 I2A_Byrack_Info3_HW_Ver_Byte8 "IMM硬件版本字节8";
CM_ SG_ 2332156725 I2A_Byrack_Info3_HW_Ver_Byte1 "IMM硬件版本字节1";
CM_ SG_ 2332156725 I2A_Byrack_Info3_HW_Ver_Byte2 "IMM硬件版本字节2";
CM_ SG_ 2332156725 I2A_Byrack_Info3_HW_Ver_Byte3 "IMM硬件版本字节3";
CM_ SG_ 2332156725 I2A_Byrack_Info3_HW_Ver_Byte4 "IMM硬件版本字节4";
CM_ SG_ 2332156725 I2A_Byrack_Info3_HW_Ver_Byte5 "IMM硬件版本字节5";
CM_ SG_ 2332156725 I2A_Byrack_Info3_HW_Ver_Byte6 "IMM硬件版本字节6";
CM_ SG_ 2332156725 I2A_Byrack_Info3_HW_Ver_Byte7 "IMM硬件版本字节7";
CM_ SG_ 2332156725 I2A_Byrack_Info3_HW_Ver_Byte8 "IMM硬件版本字节8";
CM_ SG_ 2332156726 I2A_Byrack_Info3_HW_Ver_Byte1 "IMM硬件版本字节1";
CM_ SG_ 2332156726 I2A_Byrack_Info3_HW_Ver_Byte2 "IMM硬件版本字节2";
CM_ SG_ 2332156726 I2A_Byrack_Info3_HW_Ver_Byte3 "IMM硬件版本字节3";
CM_ SG_ 2332156726 I2A_Byrack_Info3_HW_Ver_Byte4 "IMM硬件版本字节4";
CM_ SG_ 2332156726 I2A_Byrack_Info3_HW_Ver_Byte5 "IMM硬件版本字节5";
CM_ SG_ 2332156726 I2A_Byrack_Info3_HW_Ver_Byte6 "IMM硬件版本字节6";
CM_ SG_ 2332156726 I2A_Byrack_Info3_HW_Ver_Byte7 "IMM硬件版本字节7";
CM_ SG_ 2332156726 I2A_Byrack_Info3_HW_Ver_Byte8 "IMM硬件版本字节8";
CM_ SG_ 2332156727 I2A_Byrack_Info3_HW_Ver_Byte1 "IMM硬件版本字节1";
CM_ SG_ 2332156727 I2A_Byrack_Info3_HW_Ver_Byte2 "IMM硬件版本字节2";
CM_ SG_ 2332156727 I2A_Byrack_Info3_HW_Ver_Byte3 "IMM硬件版本字节3";
CM_ SG_ 2332156727 I2A_Byrack_Info3_HW_Ver_Byte4 "IMM硬件版本字节4";
CM_ SG_ 2332156727 I2A_Byrack_Info3_HW_Ver_Byte5 "IMM硬件版本字节5";
CM_ SG_ 2332156727 I2A_Byrack_Info3_HW_Ver_Byte6 "IMM硬件版本字节6";
CM_ SG_ 2332156727 I2A_Byrack_Info3_HW_Ver_Byte7 "IMM硬件版本字节7";
CM_ SG_ 2332156727 I2A_Byrack_Info3_HW_Ver_Byte8 "IMM硬件版本字节8";
CM_ SG_ 2332156728 I2A_Byrack_Info3_HW_Ver_Byte1 "IMM硬件版本字节1";
CM_ SG_ 2332156728 I2A_Byrack_Info3_HW_Ver_Byte2 "IMM硬件版本字节2";
CM_ SG_ 2332156728 I2A_Byrack_Info3_HW_Ver_Byte3 "IMM硬件版本字节3";
CM_ SG_ 2332156728 I2A_Byrack_Info3_HW_Ver_Byte4 "IMM硬件版本字节4";
CM_ SG_ 2332156728 I2A_Byrack_Info3_HW_Ver_Byte5 "IMM硬件版本字节5";
CM_ SG_ 2332156728 I2A_Byrack_Info3_HW_Ver_Byte6 "IMM硬件版本字节6";
CM_ SG_ 2332156728 I2A_Byrack_Info3_HW_Ver_Byte7 "IMM硬件版本字节7";
CM_ SG_ 2332156728 I2A_Byrack_Info3_HW_Ver_Byte8 "IMM硬件版本字节8";
CM_ SG_ 2332156729 I2A_Byrack_Info3_HW_Ver_Byte1 "IMM硬件版本字节1";
CM_ SG_ 2332156729 I2A_Byrack_Info3_HW_Ver_Byte2 "IMM硬件版本字节2";
CM_ SG_ 2332156729 I2A_Byrack_Info3_HW_Ver_Byte3 "IMM硬件版本字节3";
CM_ SG_ 2332156729 I2A_Byrack_Info3_HW_Ver_Byte4 "IMM硬件版本字节4";
CM_ SG_ 2332156729 I2A_Byrack_Info3_HW_Ver_Byte5 "IMM硬件版本字节5";
CM_ SG_ 2332156729 I2A_Byrack_Info3_HW_Ver_Byte6 "IMM硬件版本字节6";
CM_ SG_ 2332156729 I2A_Byrack_Info3_HW_Ver_Byte7 "IMM硬件版本字节7";
CM_ SG_ 2332156729 I2A_Byrack_Info3_HW_Ver_Byte8 "IMM硬件版本字节8";
CM_ SG_ 2332156730 I2A_Byrack_Info3_HW_Ver_Byte1 "IMM硬件版本字节1";
CM_ SG_ 2332156730 I2A_Byrack_Info3_HW_Ver_Byte2 "IMM硬件版本字节2";
CM_ SG_ 2332156730 I2A_Byrack_Info3_HW_Ver_Byte3 "IMM硬件版本字节3";
CM_ SG_ 2332156730 I2A_Byrack_Info3_HW_Ver_Byte4 "IMM硬件版本字节4";
CM_ SG_ 2332156730 I2A_Byrack_Info3_HW_Ver_Byte5 "IMM硬件版本字节5";
CM_ SG_ 2332156730 I2A_Byrack_Info3_HW_Ver_Byte6 "IMM硬件版本字节6";
CM_ SG_ 2332156730 I2A_Byrack_Info3_HW_Ver_Byte7 "IMM硬件版本字节7";
CM_ SG_ 2332156730 I2A_Byrack_Info3_HW_Ver_Byte8 "IMM硬件版本字节8";
CM_ SG_ 2332156731 I2A_Byrack_Info3_HW_Ver_Byte1 "IMM硬件版本字节1";
CM_ SG_ 2332156731 I2A_Byrack_Info3_HW_Ver_Byte2 "IMM硬件版本字节2";
CM_ SG_ 2332156731 I2A_Byrack_Info3_HW_Ver_Byte3 "IMM硬件版本字节3";
CM_ SG_ 2332156731 I2A_Byrack_Info3_HW_Ver_Byte4 "IMM硬件版本字节4";
CM_ SG_ 2332156731 I2A_Byrack_Info3_HW_Ver_Byte5 "IMM硬件版本字节5";
CM_ SG_ 2332156731 I2A_Byrack_Info3_HW_Ver_Byte6 "IMM硬件版本字节6";
CM_ SG_ 2332156731 I2A_Byrack_Info3_HW_Ver_Byte7 "IMM硬件版本字节7";
CM_ SG_ 2332156731 I2A_Byrack_Info3_HW_Ver_Byte8 "IMM硬件版本字节8";
CM_ SG_ 2332156732 I2A_Byrack_Info3_HW_Ver_Byte1 "IMM硬件版本字节1";
CM_ SG_ 2332156732 I2A_Byrack_Info3_HW_Ver_Byte2 "IMM硬件版本字节2";
CM_ SG_ 2332156732 I2A_Byrack_Info3_HW_Ver_Byte3 "IMM硬件版本字节3";
CM_ SG_ 2332156732 I2A_Byrack_Info3_HW_Ver_Byte4 "IMM硬件版本字节4";
CM_ SG_ 2332156732 I2A_Byrack_Info3_HW_Ver_Byte5 "IMM硬件版本字节5";
CM_ SG_ 2332156732 I2A_Byrack_Info3_HW_Ver_Byte6 "IMM硬件版本字节6";
CM_ SG_ 2332156732 I2A_Byrack_Info3_HW_Ver_Byte7 "IMM硬件版本字节7";
CM_ SG_ 2332156732 I2A_Byrack_Info3_HW_Ver_Byte8 "IMM硬件版本字节8";
CM_ SG_ 2332156733 I2A_Byrack_Info3_HW_Ver_Byte1 "IMM硬件版本字节1";
CM_ SG_ 2332156733 I2A_Byrack_Info3_HW_Ver_Byte2 "IMM硬件版本字节2";
CM_ SG_ 2332156733 I2A_Byrack_Info3_HW_Ver_Byte3 "IMM硬件版本字节3";
CM_ SG_ 2332156733 I2A_Byrack_Info3_HW_Ver_Byte4 "IMM硬件版本字节4";
CM_ SG_ 2332156733 I2A_Byrack_Info3_HW_Ver_Byte5 "IMM硬件版本字节5";
CM_ SG_ 2332156733 I2A_Byrack_Info3_HW_Ver_Byte6 "IMM硬件版本字节6";
CM_ SG_ 2332156733 I2A_Byrack_Info3_HW_Ver_Byte7 "IMM硬件版本字节7";
CM_ SG_ 2332156733 I2A_Byrack_Info3_HW_Ver_Byte8 "IMM硬件版本字节8";
CM_ SG_ 2332156734 I2A_Byrack_Info3_HW_Ver_Byte1 "IMM硬件版本字节1";
CM_ SG_ 2332156734 I2A_Byrack_Info3_HW_Ver_Byte2 "IMM硬件版本字节2";
CM_ SG_ 2332156734 I2A_Byrack_Info3_HW_Ver_Byte3 "IMM硬件版本字节3";
CM_ SG_ 2332156734 I2A_Byrack_Info3_HW_Ver_Byte4 "IMM硬件版本字节4";
CM_ SG_ 2332156734 I2A_Byrack_Info3_HW_Ver_Byte5 "IMM硬件版本字节5";
CM_ SG_ 2332156734 I2A_Byrack_Info3_HW_Ver_Byte6 "IMM硬件版本字节6";
CM_ SG_ 2332156734 I2A_Byrack_Info3_HW_Ver_Byte7 "IMM硬件版本字节7";
CM_ SG_ 2332156734 I2A_Byrack_Info3_HW_Ver_Byte8 "IMM硬件版本字节8";
CM_ SG_ 2332156735 I2A_Byrack_Info3_HW_Ver_Byte1 "IMM硬件版本字节1";
CM_ SG_ 2332156735 I2A_Byrack_Info3_HW_Ver_Byte2 "IMM硬件版本字节2";
CM_ SG_ 2332156735 I2A_Byrack_Info3_HW_Ver_Byte3 "IMM硬件版本字节3";
CM_ SG_ 2332156735 I2A_Byrack_Info3_HW_Ver_Byte4 "IMM硬件版本字节4";
CM_ SG_ 2332156735 I2A_Byrack_Info3_HW_Ver_Byte5 "IMM硬件版本字节5";
CM_ SG_ 2332156735 I2A_Byrack_Info3_HW_Ver_Byte6 "IMM硬件版本字节6";
CM_ SG_ 2332156735 I2A_Byrack_Info3_HW_Ver_Byte7 "IMM硬件版本字节7";
CM_ SG_ 2332156735 I2A_Byrack_Info3_HW_Ver_Byte8 "IMM硬件版本字节8";
CM_ SG_ 2332156961 I2A_Byrack_Info4_HW_Ver_Byte9 "IMM硬件版本字节9";
CM_ SG_ 2332156961 I2A_Byrack_Info4_HW_Ver_Byte10 "IMM硬件版本字节10";
CM_ SG_ 2332156961 I2A_Byrack_Info4_HW_Ver_Byte11 "IMM硬件版本字节11";
CM_ SG_ 2332156961 I2A_Byrack_Info4_HW_Ver_Byte12 "IMM硬件版本字节12";
CM_ SG_ 2332156961 I2A_Byrack_Info4_HW_Ver_Byte13 "IMM硬件版本字节13";
CM_ SG_ 2332156961 I2A_Byrack_Info4_HW_Ver_Byte14 "IMM硬件版本字节14";
CM_ SG_ 2332156961 I2A_Byrack_Info4_HW_Ver_Byte15 "IMM硬件版本字节15";
CM_ SG_ 2332156961 I2A_Byrack_Info4_HW_Ver_Byte16 "IMM硬件版本字节16";
CM_ SG_ 2332156962 I2A_Byrack_Info4_HW_Ver_Byte9 "IMM硬件版本字节9";
CM_ SG_ 2332156962 I2A_Byrack_Info4_HW_Ver_Byte10 "IMM硬件版本字节10";
CM_ SG_ 2332156962 I2A_Byrack_Info4_HW_Ver_Byte11 "IMM硬件版本字节11";
CM_ SG_ 2332156962 I2A_Byrack_Info4_HW_Ver_Byte12 "IMM硬件版本字节12";
CM_ SG_ 2332156962 I2A_Byrack_Info4_HW_Ver_Byte13 "IMM硬件版本字节13";
CM_ SG_ 2332156962 I2A_Byrack_Info4_HW_Ver_Byte14 "IMM硬件版本字节14";
CM_ SG_ 2332156962 I2A_Byrack_Info4_HW_Ver_Byte15 "IMM硬件版本字节15";
CM_ SG_ 2332156962 I2A_Byrack_Info4_HW_Ver_Byte16 "IMM硬件版本字节16";
CM_ SG_ 2332156963 I2A_Byrack_Info4_HW_Ver_Byte9 "IMM硬件版本字节9";
CM_ SG_ 2332156963 I2A_Byrack_Info4_HW_Ver_Byte10 "IMM硬件版本字节10";
CM_ SG_ 2332156963 I2A_Byrack_Info4_HW_Ver_Byte11 "IMM硬件版本字节11";
CM_ SG_ 2332156963 I2A_Byrack_Info4_HW_Ver_Byte12 "IMM硬件版本字节12";
CM_ SG_ 2332156963 I2A_Byrack_Info4_HW_Ver_Byte13 "IMM硬件版本字节13";
CM_ SG_ 2332156963 I2A_Byrack_Info4_HW_Ver_Byte14 "IMM硬件版本字节14";
CM_ SG_ 2332156963 I2A_Byrack_Info4_HW_Ver_Byte15 "IMM硬件版本字节15";
CM_ SG_ 2332156963 I2A_Byrack_Info4_HW_Ver_Byte16 "IMM硬件版本字节16";
CM_ SG_ 2332156964 I2A_Byrack_Info4_HW_Ver_Byte9 "IMM硬件版本字节9";
CM_ SG_ 2332156964 I2A_Byrack_Info4_HW_Ver_Byte10 "IMM硬件版本字节10";
CM_ SG_ 2332156964 I2A_Byrack_Info4_HW_Ver_Byte11 "IMM硬件版本字节11";
CM_ SG_ 2332156964 I2A_Byrack_Info4_HW_Ver_Byte12 "IMM硬件版本字节12";
CM_ SG_ 2332156964 I2A_Byrack_Info4_HW_Ver_Byte13 "IMM硬件版本字节13";
CM_ SG_ 2332156964 I2A_Byrack_Info4_HW_Ver_Byte14 "IMM硬件版本字节14";
CM_ SG_ 2332156964 I2A_Byrack_Info4_HW_Ver_Byte15 "IMM硬件版本字节15";
CM_ SG_ 2332156964 I2A_Byrack_Info4_HW_Ver_Byte16 "IMM硬件版本字节16";
CM_ SG_ 2332156965 I2A_Byrack_Info4_HW_Ver_Byte9 "IMM硬件版本字节9";
CM_ SG_ 2332156965 I2A_Byrack_Info4_HW_Ver_Byte10 "IMM硬件版本字节10";
CM_ SG_ 2332156965 I2A_Byrack_Info4_HW_Ver_Byte11 "IMM硬件版本字节11";
CM_ SG_ 2332156965 I2A_Byrack_Info4_HW_Ver_Byte12 "IMM硬件版本字节12";
CM_ SG_ 2332156965 I2A_Byrack_Info4_HW_Ver_Byte13 "IMM硬件版本字节13";
CM_ SG_ 2332156965 I2A_Byrack_Info4_HW_Ver_Byte14 "IMM硬件版本字节14";
CM_ SG_ 2332156965 I2A_Byrack_Info4_HW_Ver_Byte15 "IMM硬件版本字节15";
CM_ SG_ 2332156965 I2A_Byrack_Info4_HW_Ver_Byte16 "IMM硬件版本字节16";
CM_ SG_ 2332156966 I2A_Byrack_Info4_HW_Ver_Byte9 "IMM硬件版本字节9";
CM_ SG_ 2332156966 I2A_Byrack_Info4_HW_Ver_Byte10 "IMM硬件版本字节10";
CM_ SG_ 2332156966 I2A_Byrack_Info4_HW_Ver_Byte11 "IMM硬件版本字节11";
CM_ SG_ 2332156966 I2A_Byrack_Info4_HW_Ver_Byte12 "IMM硬件版本字节12";
CM_ SG_ 2332156966 I2A_Byrack_Info4_HW_Ver_Byte13 "IMM硬件版本字节13";
CM_ SG_ 2332156966 I2A_Byrack_Info4_HW_Ver_Byte14 "IMM硬件版本字节14";
CM_ SG_ 2332156966 I2A_Byrack_Info4_HW_Ver_Byte15 "IMM硬件版本字节15";
CM_ SG_ 2332156966 I2A_Byrack_Info4_HW_Ver_Byte16 "IMM硬件版本字节16";
CM_ SG_ 2332156967 I2A_Byrack_Info4_HW_Ver_Byte9 "IMM硬件版本字节9";
CM_ SG_ 2332156967 I2A_Byrack_Info4_HW_Ver_Byte10 "IMM硬件版本字节10";
CM_ SG_ 2332156967 I2A_Byrack_Info4_HW_Ver_Byte11 "IMM硬件版本字节11";
CM_ SG_ 2332156967 I2A_Byrack_Info4_HW_Ver_Byte12 "IMM硬件版本字节12";
CM_ SG_ 2332156967 I2A_Byrack_Info4_HW_Ver_Byte13 "IMM硬件版本字节13";
CM_ SG_ 2332156967 I2A_Byrack_Info4_HW_Ver_Byte14 "IMM硬件版本字节14";
CM_ SG_ 2332156967 I2A_Byrack_Info4_HW_Ver_Byte15 "IMM硬件版本字节15";
CM_ SG_ 2332156967 I2A_Byrack_Info4_HW_Ver_Byte16 "IMM硬件版本字节16";
CM_ SG_ 2332156968 I2A_Byrack_Info4_HW_Ver_Byte9 "IMM硬件版本字节9";
CM_ SG_ 2332156968 I2A_Byrack_Info4_HW_Ver_Byte10 "IMM硬件版本字节10";
CM_ SG_ 2332156968 I2A_Byrack_Info4_HW_Ver_Byte11 "IMM硬件版本字节11";
CM_ SG_ 2332156968 I2A_Byrack_Info4_HW_Ver_Byte12 "IMM硬件版本字节12";
CM_ SG_ 2332156968 I2A_Byrack_Info4_HW_Ver_Byte13 "IMM硬件版本字节13";
CM_ SG_ 2332156968 I2A_Byrack_Info4_HW_Ver_Byte14 "IMM硬件版本字节14";
CM_ SG_ 2332156968 I2A_Byrack_Info4_HW_Ver_Byte15 "IMM硬件版本字节15";
CM_ SG_ 2332156968 I2A_Byrack_Info4_HW_Ver_Byte16 "IMM硬件版本字节16";
CM_ SG_ 2332156969 I2A_Byrack_Info4_HW_Ver_Byte9 "IMM硬件版本字节9";
CM_ SG_ 2332156969 I2A_Byrack_Info4_HW_Ver_Byte10 "IMM硬件版本字节10";
CM_ SG_ 2332156969 I2A_Byrack_Info4_HW_Ver_Byte11 "IMM硬件版本字节11";
CM_ SG_ 2332156969 I2A_Byrack_Info4_HW_Ver_Byte12 "IMM硬件版本字节12";
CM_ SG_ 2332156969 I2A_Byrack_Info4_HW_Ver_Byte13 "IMM硬件版本字节13";
CM_ SG_ 2332156969 I2A_Byrack_Info4_HW_Ver_Byte14 "IMM硬件版本字节14";
CM_ SG_ 2332156969 I2A_Byrack_Info4_HW_Ver_Byte15 "IMM硬件版本字节15";
CM_ SG_ 2332156969 I2A_Byrack_Info4_HW_Ver_Byte16 "IMM硬件版本字节16";
CM_ SG_ 2332156970 I2A_Byrack_Info4_HW_Ver_Byte9 "IMM硬件版本字节9";
CM_ SG_ 2332156970 I2A_Byrack_Info4_HW_Ver_Byte10 "IMM硬件版本字节10";
CM_ SG_ 2332156970 I2A_Byrack_Info4_HW_Ver_Byte11 "IMM硬件版本字节11";
CM_ SG_ 2332156970 I2A_Byrack_Info4_HW_Ver_Byte12 "IMM硬件版本字节12";
CM_ SG_ 2332156970 I2A_Byrack_Info4_HW_Ver_Byte13 "IMM硬件版本字节13";
CM_ SG_ 2332156970 I2A_Byrack_Info4_HW_Ver_Byte14 "IMM硬件版本字节14";
CM_ SG_ 2332156970 I2A_Byrack_Info4_HW_Ver_Byte15 "IMM硬件版本字节15";
CM_ SG_ 2332156970 I2A_Byrack_Info4_HW_Ver_Byte16 "IMM硬件版本字节16";
CM_ SG_ 2332156971 I2A_Byrack_Info4_HW_Ver_Byte9 "IMM硬件版本字节9";
CM_ SG_ 2332156971 I2A_Byrack_Info4_HW_Ver_Byte10 "IMM硬件版本字节10";
CM_ SG_ 2332156971 I2A_Byrack_Info4_HW_Ver_Byte11 "IMM硬件版本字节11";
CM_ SG_ 2332156971 I2A_Byrack_Info4_HW_Ver_Byte12 "IMM硬件版本字节12";
CM_ SG_ 2332156971 I2A_Byrack_Info4_HW_Ver_Byte13 "IMM硬件版本字节13";
CM_ SG_ 2332156971 I2A_Byrack_Info4_HW_Ver_Byte14 "IMM硬件版本字节14";
CM_ SG_ 2332156971 I2A_Byrack_Info4_HW_Ver_Byte15 "IMM硬件版本字节15";
CM_ SG_ 2332156971 I2A_Byrack_Info4_HW_Ver_Byte16 "IMM硬件版本字节16";
CM_ SG_ 2332156972 I2A_Byrack_Info4_HW_Ver_Byte9 "IMM硬件版本字节9";
CM_ SG_ 2332156972 I2A_Byrack_Info4_HW_Ver_Byte10 "IMM硬件版本字节10";
CM_ SG_ 2332156972 I2A_Byrack_Info4_HW_Ver_Byte11 "IMM硬件版本字节11";
CM_ SG_ 2332156972 I2A_Byrack_Info4_HW_Ver_Byte12 "IMM硬件版本字节12";
CM_ SG_ 2332156972 I2A_Byrack_Info4_HW_Ver_Byte13 "IMM硬件版本字节13";
CM_ SG_ 2332156972 I2A_Byrack_Info4_HW_Ver_Byte14 "IMM硬件版本字节14";
CM_ SG_ 2332156972 I2A_Byrack_Info4_HW_Ver_Byte15 "IMM硬件版本字节15";
CM_ SG_ 2332156972 I2A_Byrack_Info4_HW_Ver_Byte16 "IMM硬件版本字节16";
CM_ SG_ 2332156973 I2A_Byrack_Info4_HW_Ver_Byte9 "IMM硬件版本字节9";
CM_ SG_ 2332156973 I2A_Byrack_Info4_HW_Ver_Byte10 "IMM硬件版本字节10";
CM_ SG_ 2332156973 I2A_Byrack_Info4_HW_Ver_Byte11 "IMM硬件版本字节11";
CM_ SG_ 2332156973 I2A_Byrack_Info4_HW_Ver_Byte12 "IMM硬件版本字节12";
CM_ SG_ 2332156973 I2A_Byrack_Info4_HW_Ver_Byte13 "IMM硬件版本字节13";
CM_ SG_ 2332156973 I2A_Byrack_Info4_HW_Ver_Byte14 "IMM硬件版本字节14";
CM_ SG_ 2332156973 I2A_Byrack_Info4_HW_Ver_Byte15 "IMM硬件版本字节15";
CM_ SG_ 2332156973 I2A_Byrack_Info4_HW_Ver_Byte16 "IMM硬件版本字节16";
CM_ SG_ 2332156974 I2A_Byrack_Info4_HW_Ver_Byte9 "IMM硬件版本字节9";
CM_ SG_ 2332156974 I2A_Byrack_Info4_HW_Ver_Byte10 "IMM硬件版本字节10";
CM_ SG_ 2332156974 I2A_Byrack_Info4_HW_Ver_Byte11 "IMM硬件版本字节11";
CM_ SG_ 2332156974 I2A_Byrack_Info4_HW_Ver_Byte12 "IMM硬件版本字节12";
CM_ SG_ 2332156974 I2A_Byrack_Info4_HW_Ver_Byte13 "IMM硬件版本字节13";
CM_ SG_ 2332156974 I2A_Byrack_Info4_HW_Ver_Byte14 "IMM硬件版本字节14";
CM_ SG_ 2332156974 I2A_Byrack_Info4_HW_Ver_Byte15 "IMM硬件版本字节15";
CM_ SG_ 2332156974 I2A_Byrack_Info4_HW_Ver_Byte16 "IMM硬件版本字节16";
CM_ SG_ 2332156975 I2A_Byrack_Info4_HW_Ver_Byte9 "IMM硬件版本字节9";
CM_ SG_ 2332156975 I2A_Byrack_Info4_HW_Ver_Byte10 "IMM硬件版本字节10";
CM_ SG_ 2332156975 I2A_Byrack_Info4_HW_Ver_Byte11 "IMM硬件版本字节11";
CM_ SG_ 2332156975 I2A_Byrack_Info4_HW_Ver_Byte12 "IMM硬件版本字节12";
CM_ SG_ 2332156975 I2A_Byrack_Info4_HW_Ver_Byte13 "IMM硬件版本字节13";
CM_ SG_ 2332156975 I2A_Byrack_Info4_HW_Ver_Byte14 "IMM硬件版本字节14";
CM_ SG_ 2332156975 I2A_Byrack_Info4_HW_Ver_Byte15 "IMM硬件版本字节15";
CM_ SG_ 2332156975 I2A_Byrack_Info4_HW_Ver_Byte16 "IMM硬件版本字节16";
CM_ SG_ 2332156976 I2A_Byrack_Info4_HW_Ver_Byte9 "IMM硬件版本字节9";
CM_ SG_ 2332156976 I2A_Byrack_Info4_HW_Ver_Byte10 "IMM硬件版本字节10";
CM_ SG_ 2332156976 I2A_Byrack_Info4_HW_Ver_Byte11 "IMM硬件版本字节11";
CM_ SG_ 2332156976 I2A_Byrack_Info4_HW_Ver_Byte12 "IMM硬件版本字节12";
CM_ SG_ 2332156976 I2A_Byrack_Info4_HW_Ver_Byte13 "IMM硬件版本字节13";
CM_ SG_ 2332156976 I2A_Byrack_Info4_HW_Ver_Byte14 "IMM硬件版本字节14";
CM_ SG_ 2332156976 I2A_Byrack_Info4_HW_Ver_Byte15 "IMM硬件版本字节15";
CM_ SG_ 2332156976 I2A_Byrack_Info4_HW_Ver_Byte16 "IMM硬件版本字节16";
CM_ SG_ 2332156977 I2A_Byrack_Info4_HW_Ver_Byte9 "IMM硬件版本字节9";
CM_ SG_ 2332156977 I2A_Byrack_Info4_HW_Ver_Byte10 "IMM硬件版本字节10";
CM_ SG_ 2332156977 I2A_Byrack_Info4_HW_Ver_Byte11 "IMM硬件版本字节11";
CM_ SG_ 2332156977 I2A_Byrack_Info4_HW_Ver_Byte12 "IMM硬件版本字节12";
CM_ SG_ 2332156977 I2A_Byrack_Info4_HW_Ver_Byte13 "IMM硬件版本字节13";
CM_ SG_ 2332156977 I2A_Byrack_Info4_HW_Ver_Byte14 "IMM硬件版本字节14";
CM_ SG_ 2332156977 I2A_Byrack_Info4_HW_Ver_Byte15 "IMM硬件版本字节15";
CM_ SG_ 2332156977 I2A_Byrack_Info4_HW_Ver_Byte16 "IMM硬件版本字节16";
CM_ SG_ 2332156978 I2A_Byrack_Info4_HW_Ver_Byte9 "IMM硬件版本字节9";
CM_ SG_ 2332156978 I2A_Byrack_Info4_HW_Ver_Byte10 "IMM硬件版本字节10";
CM_ SG_ 2332156978 I2A_Byrack_Info4_HW_Ver_Byte11 "IMM硬件版本字节11";
CM_ SG_ 2332156978 I2A_Byrack_Info4_HW_Ver_Byte12 "IMM硬件版本字节12";
CM_ SG_ 2332156978 I2A_Byrack_Info4_HW_Ver_Byte13 "IMM硬件版本字节13";
CM_ SG_ 2332156978 I2A_Byrack_Info4_HW_Ver_Byte14 "IMM硬件版本字节14";
CM_ SG_ 2332156978 I2A_Byrack_Info4_HW_Ver_Byte15 "IMM硬件版本字节15";
CM_ SG_ 2332156978 I2A_Byrack_Info4_HW_Ver_Byte16 "IMM硬件版本字节16";
CM_ SG_ 2332156979 I2A_Byrack_Info4_HW_Ver_Byte9 "IMM硬件版本字节9";
CM_ SG_ 2332156979 I2A_Byrack_Info4_HW_Ver_Byte10 "IMM硬件版本字节10";
CM_ SG_ 2332156979 I2A_Byrack_Info4_HW_Ver_Byte11 "IMM硬件版本字节11";
CM_ SG_ 2332156979 I2A_Byrack_Info4_HW_Ver_Byte12 "IMM硬件版本字节12";
CM_ SG_ 2332156979 I2A_Byrack_Info4_HW_Ver_Byte13 "IMM硬件版本字节13";
CM_ SG_ 2332156979 I2A_Byrack_Info4_HW_Ver_Byte14 "IMM硬件版本字节14";
CM_ SG_ 2332156979 I2A_Byrack_Info4_HW_Ver_Byte15 "IMM硬件版本字节15";
CM_ SG_ 2332156979 I2A_Byrack_Info4_HW_Ver_Byte16 "IMM硬件版本字节16";
CM_ SG_ 2332156980 I2A_Byrack_Info4_HW_Ver_Byte9 "IMM硬件版本字节9";
CM_ SG_ 2332156980 I2A_Byrack_Info4_HW_Ver_Byte10 "IMM硬件版本字节10";
CM_ SG_ 2332156980 I2A_Byrack_Info4_HW_Ver_Byte11 "IMM硬件版本字节11";
CM_ SG_ 2332156980 I2A_Byrack_Info4_HW_Ver_Byte12 "IMM硬件版本字节12";
CM_ SG_ 2332156980 I2A_Byrack_Info4_HW_Ver_Byte13 "IMM硬件版本字节13";
CM_ SG_ 2332156980 I2A_Byrack_Info4_HW_Ver_Byte14 "IMM硬件版本字节14";
CM_ SG_ 2332156980 I2A_Byrack_Info4_HW_Ver_Byte15 "IMM硬件版本字节15";
CM_ SG_ 2332156980 I2A_Byrack_Info4_HW_Ver_Byte16 "IMM硬件版本字节16";
CM_ SG_ 2332156981 I2A_Byrack_Info4_HW_Ver_Byte9 "IMM硬件版本字节9";
CM_ SG_ 2332156981 I2A_Byrack_Info4_HW_Ver_Byte10 "IMM硬件版本字节10";
CM_ SG_ 2332156981 I2A_Byrack_Info4_HW_Ver_Byte11 "IMM硬件版本字节11";
CM_ SG_ 2332156981 I2A_Byrack_Info4_HW_Ver_Byte12 "IMM硬件版本字节12";
CM_ SG_ 2332156981 I2A_Byrack_Info4_HW_Ver_Byte13 "IMM硬件版本字节13";
CM_ SG_ 2332156981 I2A_Byrack_Info4_HW_Ver_Byte14 "IMM硬件版本字节14";
CM_ SG_ 2332156981 I2A_Byrack_Info4_HW_Ver_Byte15 "IMM硬件版本字节15";
CM_ SG_ 2332156981 I2A_Byrack_Info4_HW_Ver_Byte16 "IMM硬件版本字节16";
CM_ SG_ 2332156982 I2A_Byrack_Info4_HW_Ver_Byte9 "IMM硬件版本字节9";
CM_ SG_ 2332156982 I2A_Byrack_Info4_HW_Ver_Byte10 "IMM硬件版本字节10";
CM_ SG_ 2332156982 I2A_Byrack_Info4_HW_Ver_Byte11 "IMM硬件版本字节11";
CM_ SG_ 2332156982 I2A_Byrack_Info4_HW_Ver_Byte12 "IMM硬件版本字节12";
CM_ SG_ 2332156982 I2A_Byrack_Info4_HW_Ver_Byte13 "IMM硬件版本字节13";
CM_ SG_ 2332156982 I2A_Byrack_Info4_HW_Ver_Byte14 "IMM硬件版本字节14";
CM_ SG_ 2332156982 I2A_Byrack_Info4_HW_Ver_Byte15 "IMM硬件版本字节15";
CM_ SG_ 2332156982 I2A_Byrack_Info4_HW_Ver_Byte16 "IMM硬件版本字节16";
CM_ SG_ 2332156983 I2A_Byrack_Info4_HW_Ver_Byte9 "IMM硬件版本字节9";
CM_ SG_ 2332156983 I2A_Byrack_Info4_HW_Ver_Byte10 "IMM硬件版本字节10";
CM_ SG_ 2332156983 I2A_Byrack_Info4_HW_Ver_Byte11 "IMM硬件版本字节11";
CM_ SG_ 2332156983 I2A_Byrack_Info4_HW_Ver_Byte12 "IMM硬件版本字节12";
CM_ SG_ 2332156983 I2A_Byrack_Info4_HW_Ver_Byte13 "IMM硬件版本字节13";
CM_ SG_ 2332156983 I2A_Byrack_Info4_HW_Ver_Byte14 "IMM硬件版本字节14";
CM_ SG_ 2332156983 I2A_Byrack_Info4_HW_Ver_Byte15 "IMM硬件版本字节15";
CM_ SG_ 2332156983 I2A_Byrack_Info4_HW_Ver_Byte16 "IMM硬件版本字节16";
CM_ SG_ 2332156984 I2A_Byrack_Info4_HW_Ver_Byte9 "IMM硬件版本字节9";
CM_ SG_ 2332156984 I2A_Byrack_Info4_HW_Ver_Byte10 "IMM硬件版本字节10";
CM_ SG_ 2332156984 I2A_Byrack_Info4_HW_Ver_Byte11 "IMM硬件版本字节11";
CM_ SG_ 2332156984 I2A_Byrack_Info4_HW_Ver_Byte12 "IMM硬件版本字节12";
CM_ SG_ 2332156984 I2A_Byrack_Info4_HW_Ver_Byte13 "IMM硬件版本字节13";
CM_ SG_ 2332156984 I2A_Byrack_Info4_HW_Ver_Byte14 "IMM硬件版本字节14";
CM_ SG_ 2332156984 I2A_Byrack_Info4_HW_Ver_Byte15 "IMM硬件版本字节15";
CM_ SG_ 2332156984 I2A_Byrack_Info4_HW_Ver_Byte16 "IMM硬件版本字节16";
CM_ SG_ 2332156985 I2A_Byrack_Info4_HW_Ver_Byte9 "IMM硬件版本字节9";
CM_ SG_ 2332156985 I2A_Byrack_Info4_HW_Ver_Byte10 "IMM硬件版本字节10";
CM_ SG_ 2332156985 I2A_Byrack_Info4_HW_Ver_Byte11 "IMM硬件版本字节11";
CM_ SG_ 2332156985 I2A_Byrack_Info4_HW_Ver_Byte12 "IMM硬件版本字节12";
CM_ SG_ 2332156985 I2A_Byrack_Info4_HW_Ver_Byte13 "IMM硬件版本字节13";
CM_ SG_ 2332156985 I2A_Byrack_Info4_HW_Ver_Byte14 "IMM硬件版本字节14";
CM_ SG_ 2332156985 I2A_Byrack_Info4_HW_Ver_Byte15 "IMM硬件版本字节15";
CM_ SG_ 2332156985 I2A_Byrack_Info4_HW_Ver_Byte16 "IMM硬件版本字节16";
CM_ SG_ 2332156986 I2A_Byrack_Info4_HW_Ver_Byte9 "IMM硬件版本字节9";
CM_ SG_ 2332156986 I2A_Byrack_Info4_HW_Ver_Byte10 "IMM硬件版本字节10";
CM_ SG_ 2332156986 I2A_Byrack_Info4_HW_Ver_Byte11 "IMM硬件版本字节11";
CM_ SG_ 2332156986 I2A_Byrack_Info4_HW_Ver_Byte12 "IMM硬件版本字节12";
CM_ SG_ 2332156986 I2A_Byrack_Info4_HW_Ver_Byte13 "IMM硬件版本字节13";
CM_ SG_ 2332156986 I2A_Byrack_Info4_HW_Ver_Byte14 "IMM硬件版本字节14";
CM_ SG_ 2332156986 I2A_Byrack_Info4_HW_Ver_Byte15 "IMM硬件版本字节15";
CM_ SG_ 2332156986 I2A_Byrack_Info4_HW_Ver_Byte16 "IMM硬件版本字节16";
CM_ SG_ 2332156987 I2A_Byrack_Info4_HW_Ver_Byte9 "IMM硬件版本字节9";
CM_ SG_ 2332156987 I2A_Byrack_Info4_HW_Ver_Byte10 "IMM硬件版本字节10";
CM_ SG_ 2332156987 I2A_Byrack_Info4_HW_Ver_Byte11 "IMM硬件版本字节11";
CM_ SG_ 2332156987 I2A_Byrack_Info4_HW_Ver_Byte12 "IMM硬件版本字节12";
CM_ SG_ 2332156987 I2A_Byrack_Info4_HW_Ver_Byte13 "IMM硬件版本字节13";
CM_ SG_ 2332156987 I2A_Byrack_Info4_HW_Ver_Byte14 "IMM硬件版本字节14";
CM_ SG_ 2332156987 I2A_Byrack_Info4_HW_Ver_Byte15 "IMM硬件版本字节15";
CM_ SG_ 2332156987 I2A_Byrack_Info4_HW_Ver_Byte16 "IMM硬件版本字节16";
CM_ SG_ 2332156988 I2A_Byrack_Info4_HW_Ver_Byte9 "IMM硬件版本字节9";
CM_ SG_ 2332156988 I2A_Byrack_Info4_HW_Ver_Byte10 "IMM硬件版本字节10";
CM_ SG_ 2332156988 I2A_Byrack_Info4_HW_Ver_Byte11 "IMM硬件版本字节11";
CM_ SG_ 2332156988 I2A_Byrack_Info4_HW_Ver_Byte12 "IMM硬件版本字节12";
CM_ SG_ 2332156988 I2A_Byrack_Info4_HW_Ver_Byte13 "IMM硬件版本字节13";
CM_ SG_ 2332156988 I2A_Byrack_Info4_HW_Ver_Byte14 "IMM硬件版本字节14";
CM_ SG_ 2332156988 I2A_Byrack_Info4_HW_Ver_Byte15 "IMM硬件版本字节15";
CM_ SG_ 2332156988 I2A_Byrack_Info4_HW_Ver_Byte16 "IMM硬件版本字节16";
CM_ SG_ 2332156989 I2A_Byrack_Info4_HW_Ver_Byte9 "IMM硬件版本字节9";
CM_ SG_ 2332156989 I2A_Byrack_Info4_HW_Ver_Byte10 "IMM硬件版本字节10";
CM_ SG_ 2332156989 I2A_Byrack_Info4_HW_Ver_Byte11 "IMM硬件版本字节11";
CM_ SG_ 2332156989 I2A_Byrack_Info4_HW_Ver_Byte12 "IMM硬件版本字节12";
CM_ SG_ 2332156989 I2A_Byrack_Info4_HW_Ver_Byte13 "IMM硬件版本字节13";
CM_ SG_ 2332156989 I2A_Byrack_Info4_HW_Ver_Byte14 "IMM硬件版本字节14";
CM_ SG_ 2332156989 I2A_Byrack_Info4_HW_Ver_Byte15 "IMM硬件版本字节15";
CM_ SG_ 2332156989 I2A_Byrack_Info4_HW_Ver_Byte16 "IMM硬件版本字节16";
CM_ SG_ 2332156990 I2A_Byrack_Info4_HW_Ver_Byte9 "IMM硬件版本字节9";
CM_ SG_ 2332156990 I2A_Byrack_Info4_HW_Ver_Byte10 "IMM硬件版本字节10";
CM_ SG_ 2332156990 I2A_Byrack_Info4_HW_Ver_Byte11 "IMM硬件版本字节11";
CM_ SG_ 2332156990 I2A_Byrack_Info4_HW_Ver_Byte12 "IMM硬件版本字节12";
CM_ SG_ 2332156990 I2A_Byrack_Info4_HW_Ver_Byte13 "IMM硬件版本字节13";
CM_ SG_ 2332156990 I2A_Byrack_Info4_HW_Ver_Byte14 "IMM硬件版本字节14";
CM_ SG_ 2332156990 I2A_Byrack_Info4_HW_Ver_Byte15 "IMM硬件版本字节15";
CM_ SG_ 2332156990 I2A_Byrack_Info4_HW_Ver_Byte16 "IMM硬件版本字节16";
CM_ SG_ 2332156991 I2A_Byrack_Info4_HW_Ver_Byte9 "IMM硬件版本字节9";
CM_ SG_ 2332156991 I2A_Byrack_Info4_HW_Ver_Byte10 "IMM硬件版本字节10";
CM_ SG_ 2332156991 I2A_Byrack_Info4_HW_Ver_Byte11 "IMM硬件版本字节11";
CM_ SG_ 2332156991 I2A_Byrack_Info4_HW_Ver_Byte12 "IMM硬件版本字节12";
CM_ SG_ 2332156991 I2A_Byrack_Info4_HW_Ver_Byte13 "IMM硬件版本字节13";
CM_ SG_ 2332156991 I2A_Byrack_Info4_HW_Ver_Byte14 "IMM硬件版本字节14";
CM_ SG_ 2332156991 I2A_Byrack_Info4_HW_Ver_Byte15 "IMM硬件版本字节15";
CM_ SG_ 2332156991 I2A_Byrack_Info4_HW_Ver_Byte16 "IMM硬件版本字节16";
CM_ SG_ 2332157217 I2A_Byrack_Barcode1 "当前IMM的Barcode1(压缩BCD码）";
CM_ SG_ 2332157217 I2A_Byrack_Barcode2 "当前IMM的Barcode2(压缩BCD码）";
CM_ SG_ 2332157217 I2A_Byrack_Barcode3 "当前IMM的Barcode3(压缩BCD码）";
CM_ SG_ 2332157217 I2A_Byrack_Barcode4 "当前IMM的Barcode4(压缩BCD码）";
CM_ SG_ 2332157217 I2A_Byrack_Barcode5 "当前IMM的Barcode5(压缩BCD码）";
CM_ SG_ 2332157217 I2A_Byrack_Barcode6 "当前IMM的Barcode6(压缩BCD码）";
CM_ SG_ 2332157218 I2A_Byrack_Barcode1 "当前IMM的Barcode1(压缩BCD码）";
CM_ SG_ 2332157218 I2A_Byrack_Barcode2 "当前IMM的Barcode2(压缩BCD码）";
CM_ SG_ 2332157218 I2A_Byrack_Barcode3 "当前IMM的Barcode3(压缩BCD码）";
CM_ SG_ 2332157218 I2A_Byrack_Barcode4 "当前IMM的Barcode4(压缩BCD码）";
CM_ SG_ 2332157218 I2A_Byrack_Barcode5 "当前IMM的Barcode5(压缩BCD码）";
CM_ SG_ 2332157218 I2A_Byrack_Barcode6 "当前IMM的Barcode6(压缩BCD码）";
CM_ SG_ 2332157219 I2A_Byrack_Barcode1 "当前IMM的Barcode1(压缩BCD码）";
CM_ SG_ 2332157219 I2A_Byrack_Barcode2 "当前IMM的Barcode2(压缩BCD码）";
CM_ SG_ 2332157219 I2A_Byrack_Barcode3 "当前IMM的Barcode3(压缩BCD码）";
CM_ SG_ 2332157219 I2A_Byrack_Barcode4 "当前IMM的Barcode4(压缩BCD码）";
CM_ SG_ 2332157219 I2A_Byrack_Barcode5 "当前IMM的Barcode5(压缩BCD码）";
CM_ SG_ 2332157219 I2A_Byrack_Barcode6 "当前IMM的Barcode6(压缩BCD码）";
CM_ SG_ 2332157220 I2A_Byrack_Barcode1 "当前IMM的Barcode1(压缩BCD码）";
CM_ SG_ 2332157220 I2A_Byrack_Barcode2 "当前IMM的Barcode2(压缩BCD码）";
CM_ SG_ 2332157220 I2A_Byrack_Barcode3 "当前IMM的Barcode3(压缩BCD码）";
CM_ SG_ 2332157220 I2A_Byrack_Barcode4 "当前IMM的Barcode4(压缩BCD码）";
CM_ SG_ 2332157220 I2A_Byrack_Barcode5 "当前IMM的Barcode5(压缩BCD码）";
CM_ SG_ 2332157220 I2A_Byrack_Barcode6 "当前IMM的Barcode6(压缩BCD码）";
CM_ SG_ 2332157221 I2A_Byrack_Barcode1 "当前IMM的Barcode1(压缩BCD码）";
CM_ SG_ 2332157221 I2A_Byrack_Barcode2 "当前IMM的Barcode2(压缩BCD码）";
CM_ SG_ 2332157221 I2A_Byrack_Barcode3 "当前IMM的Barcode3(压缩BCD码）";
CM_ SG_ 2332157221 I2A_Byrack_Barcode4 "当前IMM的Barcode4(压缩BCD码）";
CM_ SG_ 2332157221 I2A_Byrack_Barcode5 "当前IMM的Barcode5(压缩BCD码）";
CM_ SG_ 2332157221 I2A_Byrack_Barcode6 "当前IMM的Barcode6(压缩BCD码）";
CM_ SG_ 2332157222 I2A_Byrack_Barcode1 "当前IMM的Barcode1(压缩BCD码）";
CM_ SG_ 2332157222 I2A_Byrack_Barcode2 "当前IMM的Barcode2(压缩BCD码）";
CM_ SG_ 2332157222 I2A_Byrack_Barcode3 "当前IMM的Barcode3(压缩BCD码）";
CM_ SG_ 2332157222 I2A_Byrack_Barcode4 "当前IMM的Barcode4(压缩BCD码）";
CM_ SG_ 2332157222 I2A_Byrack_Barcode5 "当前IMM的Barcode5(压缩BCD码）";
CM_ SG_ 2332157222 I2A_Byrack_Barcode6 "当前IMM的Barcode6(压缩BCD码）";
CM_ SG_ 2332157223 I2A_Byrack_Barcode1 "当前IMM的Barcode1(压缩BCD码）";
CM_ SG_ 2332157223 I2A_Byrack_Barcode2 "当前IMM的Barcode2(压缩BCD码）";
CM_ SG_ 2332157223 I2A_Byrack_Barcode3 "当前IMM的Barcode3(压缩BCD码）";
CM_ SG_ 2332157223 I2A_Byrack_Barcode4 "当前IMM的Barcode4(压缩BCD码）";
CM_ SG_ 2332157223 I2A_Byrack_Barcode5 "当前IMM的Barcode5(压缩BCD码）";
CM_ SG_ 2332157223 I2A_Byrack_Barcode6 "当前IMM的Barcode6(压缩BCD码）";
CM_ SG_ 2332157224 I2A_Byrack_Barcode1 "当前IMM的Barcode1(压缩BCD码）";
CM_ SG_ 2332157224 I2A_Byrack_Barcode2 "当前IMM的Barcode2(压缩BCD码）";
CM_ SG_ 2332157224 I2A_Byrack_Barcode3 "当前IMM的Barcode3(压缩BCD码）";
CM_ SG_ 2332157224 I2A_Byrack_Barcode4 "当前IMM的Barcode4(压缩BCD码）";
CM_ SG_ 2332157224 I2A_Byrack_Barcode5 "当前IMM的Barcode5(压缩BCD码）";
CM_ SG_ 2332157224 I2A_Byrack_Barcode6 "当前IMM的Barcode6(压缩BCD码）";
CM_ SG_ 2332157225 I2A_Byrack_Barcode1 "当前IMM的Barcode1(压缩BCD码）";
CM_ SG_ 2332157225 I2A_Byrack_Barcode2 "当前IMM的Barcode2(压缩BCD码）";
CM_ SG_ 2332157225 I2A_Byrack_Barcode3 "当前IMM的Barcode3(压缩BCD码）";
CM_ SG_ 2332157225 I2A_Byrack_Barcode4 "当前IMM的Barcode4(压缩BCD码）";
CM_ SG_ 2332157225 I2A_Byrack_Barcode5 "当前IMM的Barcode5(压缩BCD码）";
CM_ SG_ 2332157225 I2A_Byrack_Barcode6 "当前IMM的Barcode6(压缩BCD码）";
CM_ SG_ 2332157226 I2A_Byrack_Barcode1 "当前IMM的Barcode1(压缩BCD码）";
CM_ SG_ 2332157226 I2A_Byrack_Barcode2 "当前IMM的Barcode2(压缩BCD码）";
CM_ SG_ 2332157226 I2A_Byrack_Barcode3 "当前IMM的Barcode3(压缩BCD码）";
CM_ SG_ 2332157226 I2A_Byrack_Barcode4 "当前IMM的Barcode4(压缩BCD码）";
CM_ SG_ 2332157226 I2A_Byrack_Barcode5 "当前IMM的Barcode5(压缩BCD码）";
CM_ SG_ 2332157226 I2A_Byrack_Barcode6 "当前IMM的Barcode6(压缩BCD码）";
CM_ SG_ 2332157227 I2A_Byrack_Barcode1 "当前IMM的Barcode1(压缩BCD码）";
CM_ SG_ 2332157227 I2A_Byrack_Barcode2 "当前IMM的Barcode2(压缩BCD码）";
CM_ SG_ 2332157227 I2A_Byrack_Barcode3 "当前IMM的Barcode3(压缩BCD码）";
CM_ SG_ 2332157227 I2A_Byrack_Barcode4 "当前IMM的Barcode4(压缩BCD码）";
CM_ SG_ 2332157227 I2A_Byrack_Barcode5 "当前IMM的Barcode5(压缩BCD码）";
CM_ SG_ 2332157227 I2A_Byrack_Barcode6 "当前IMM的Barcode6(压缩BCD码）";
CM_ SG_ 2332157228 I2A_Byrack_Barcode1 "当前IMM的Barcode1(压缩BCD码）";
CM_ SG_ 2332157228 I2A_Byrack_Barcode2 "当前IMM的Barcode2(压缩BCD码）";
CM_ SG_ 2332157228 I2A_Byrack_Barcode3 "当前IMM的Barcode3(压缩BCD码）";
CM_ SG_ 2332157228 I2A_Byrack_Barcode4 "当前IMM的Barcode4(压缩BCD码）";
CM_ SG_ 2332157228 I2A_Byrack_Barcode5 "当前IMM的Barcode5(压缩BCD码）";
CM_ SG_ 2332157228 I2A_Byrack_Barcode6 "当前IMM的Barcode6(压缩BCD码）";
CM_ SG_ 2332157229 I2A_Byrack_Barcode1 "当前IMM的Barcode1(压缩BCD码）";
CM_ SG_ 2332157229 I2A_Byrack_Barcode2 "当前IMM的Barcode2(压缩BCD码）";
CM_ SG_ 2332157229 I2A_Byrack_Barcode3 "当前IMM的Barcode3(压缩BCD码）";
CM_ SG_ 2332157229 I2A_Byrack_Barcode4 "当前IMM的Barcode4(压缩BCD码）";
CM_ SG_ 2332157229 I2A_Byrack_Barcode5 "当前IMM的Barcode5(压缩BCD码）";
CM_ SG_ 2332157229 I2A_Byrack_Barcode6 "当前IMM的Barcode6(压缩BCD码）";
CM_ SG_ 2332157230 I2A_Byrack_Barcode1 "当前IMM的Barcode1(压缩BCD码）";
CM_ SG_ 2332157230 I2A_Byrack_Barcode2 "当前IMM的Barcode2(压缩BCD码）";
CM_ SG_ 2332157230 I2A_Byrack_Barcode3 "当前IMM的Barcode3(压缩BCD码）";
CM_ SG_ 2332157230 I2A_Byrack_Barcode4 "当前IMM的Barcode4(压缩BCD码）";
CM_ SG_ 2332157230 I2A_Byrack_Barcode5 "当前IMM的Barcode5(压缩BCD码）";
CM_ SG_ 2332157230 I2A_Byrack_Barcode6 "当前IMM的Barcode6(压缩BCD码）";
CM_ SG_ 2332157231 I2A_Byrack_Barcode1 "当前IMM的Barcode1(压缩BCD码）";
CM_ SG_ 2332157231 I2A_Byrack_Barcode2 "当前IMM的Barcode2(压缩BCD码）";
CM_ SG_ 2332157231 I2A_Byrack_Barcode3 "当前IMM的Barcode3(压缩BCD码）";
CM_ SG_ 2332157231 I2A_Byrack_Barcode4 "当前IMM的Barcode4(压缩BCD码）";
CM_ SG_ 2332157231 I2A_Byrack_Barcode5 "当前IMM的Barcode5(压缩BCD码）";
CM_ SG_ 2332157231 I2A_Byrack_Barcode6 "当前IMM的Barcode6(压缩BCD码）";
CM_ SG_ 2332157232 I2A_Byrack_Barcode1 "当前IMM的Barcode1(压缩BCD码）";
CM_ SG_ 2332157232 I2A_Byrack_Barcode2 "当前IMM的Barcode2(压缩BCD码）";
CM_ SG_ 2332157232 I2A_Byrack_Barcode3 "当前IMM的Barcode3(压缩BCD码）";
CM_ SG_ 2332157232 I2A_Byrack_Barcode4 "当前IMM的Barcode4(压缩BCD码）";
CM_ SG_ 2332157232 I2A_Byrack_Barcode5 "当前IMM的Barcode5(压缩BCD码）";
CM_ SG_ 2332157232 I2A_Byrack_Barcode6 "当前IMM的Barcode6(压缩BCD码）";
CM_ SG_ 2332157233 I2A_Byrack_Barcode1 "当前IMM的Barcode1(压缩BCD码）";
CM_ SG_ 2332157233 I2A_Byrack_Barcode2 "当前IMM的Barcode2(压缩BCD码）";
CM_ SG_ 2332157233 I2A_Byrack_Barcode3 "当前IMM的Barcode3(压缩BCD码）";
CM_ SG_ 2332157233 I2A_Byrack_Barcode4 "当前IMM的Barcode4(压缩BCD码）";
CM_ SG_ 2332157233 I2A_Byrack_Barcode5 "当前IMM的Barcode5(压缩BCD码）";
CM_ SG_ 2332157233 I2A_Byrack_Barcode6 "当前IMM的Barcode6(压缩BCD码）";
CM_ SG_ 2332157234 I2A_Byrack_Barcode1 "当前IMM的Barcode1(压缩BCD码）";
CM_ SG_ 2332157234 I2A_Byrack_Barcode2 "当前IMM的Barcode2(压缩BCD码）";
CM_ SG_ 2332157234 I2A_Byrack_Barcode3 "当前IMM的Barcode3(压缩BCD码）";
CM_ SG_ 2332157234 I2A_Byrack_Barcode4 "当前IMM的Barcode4(压缩BCD码）";
CM_ SG_ 2332157234 I2A_Byrack_Barcode5 "当前IMM的Barcode5(压缩BCD码）";
CM_ SG_ 2332157234 I2A_Byrack_Barcode6 "当前IMM的Barcode6(压缩BCD码）";
CM_ SG_ 2332157235 I2A_Byrack_Barcode1 "当前IMM的Barcode1(压缩BCD码）";
CM_ SG_ 2332157235 I2A_Byrack_Barcode2 "当前IMM的Barcode2(压缩BCD码）";
CM_ SG_ 2332157235 I2A_Byrack_Barcode3 "当前IMM的Barcode3(压缩BCD码）";
CM_ SG_ 2332157235 I2A_Byrack_Barcode4 "当前IMM的Barcode4(压缩BCD码）";
CM_ SG_ 2332157235 I2A_Byrack_Barcode5 "当前IMM的Barcode5(压缩BCD码）";
CM_ SG_ 2332157235 I2A_Byrack_Barcode6 "当前IMM的Barcode6(压缩BCD码）";
CM_ SG_ 2332157236 I2A_Byrack_Barcode1 "当前IMM的Barcode1(压缩BCD码）";
CM_ SG_ 2332157236 I2A_Byrack_Barcode2 "当前IMM的Barcode2(压缩BCD码）";
CM_ SG_ 2332157236 I2A_Byrack_Barcode3 "当前IMM的Barcode3(压缩BCD码）";
CM_ SG_ 2332157236 I2A_Byrack_Barcode4 "当前IMM的Barcode4(压缩BCD码）";
CM_ SG_ 2332157236 I2A_Byrack_Barcode5 "当前IMM的Barcode5(压缩BCD码）";
CM_ SG_ 2332157236 I2A_Byrack_Barcode6 "当前IMM的Barcode6(压缩BCD码）";
CM_ SG_ 2332157237 I2A_Byrack_Barcode1 "当前IMM的Barcode1(压缩BCD码）";
CM_ SG_ 2332157237 I2A_Byrack_Barcode2 "当前IMM的Barcode2(压缩BCD码）";
CM_ SG_ 2332157237 I2A_Byrack_Barcode3 "当前IMM的Barcode3(压缩BCD码）";
CM_ SG_ 2332157237 I2A_Byrack_Barcode4 "当前IMM的Barcode4(压缩BCD码）";
CM_ SG_ 2332157237 I2A_Byrack_Barcode5 "当前IMM的Barcode5(压缩BCD码）";
CM_ SG_ 2332157237 I2A_Byrack_Barcode6 "当前IMM的Barcode6(压缩BCD码）";
CM_ SG_ 2332157238 I2A_Byrack_Barcode1 "当前IMM的Barcode1(压缩BCD码）";
CM_ SG_ 2332157238 I2A_Byrack_Barcode2 "当前IMM的Barcode2(压缩BCD码）";
CM_ SG_ 2332157238 I2A_Byrack_Barcode3 "当前IMM的Barcode3(压缩BCD码）";
CM_ SG_ 2332157238 I2A_Byrack_Barcode4 "当前IMM的Barcode4(压缩BCD码）";
CM_ SG_ 2332157238 I2A_Byrack_Barcode5 "当前IMM的Barcode5(压缩BCD码）";
CM_ SG_ 2332157238 I2A_Byrack_Barcode6 "当前IMM的Barcode6(压缩BCD码）";
CM_ SG_ 2332157239 I2A_Byrack_Barcode1 "当前IMM的Barcode1(压缩BCD码）";
CM_ SG_ 2332157239 I2A_Byrack_Barcode2 "当前IMM的Barcode2(压缩BCD码）";
CM_ SG_ 2332157239 I2A_Byrack_Barcode3 "当前IMM的Barcode3(压缩BCD码）";
CM_ SG_ 2332157239 I2A_Byrack_Barcode4 "当前IMM的Barcode4(压缩BCD码）";
CM_ SG_ 2332157239 I2A_Byrack_Barcode5 "当前IMM的Barcode5(压缩BCD码）";
CM_ SG_ 2332157239 I2A_Byrack_Barcode6 "当前IMM的Barcode6(压缩BCD码）";
CM_ SG_ 2332157240 I2A_Byrack_Barcode1 "当前IMM的Barcode1(压缩BCD码）";
CM_ SG_ 2332157240 I2A_Byrack_Barcode2 "当前IMM的Barcode2(压缩BCD码）";
CM_ SG_ 2332157240 I2A_Byrack_Barcode3 "当前IMM的Barcode3(压缩BCD码）";
CM_ SG_ 2332157240 I2A_Byrack_Barcode4 "当前IMM的Barcode4(压缩BCD码）";
CM_ SG_ 2332157240 I2A_Byrack_Barcode5 "当前IMM的Barcode5(压缩BCD码）";
CM_ SG_ 2332157240 I2A_Byrack_Barcode6 "当前IMM的Barcode6(压缩BCD码）";
CM_ SG_ 2332157241 I2A_Byrack_Barcode1 "当前IMM的Barcode1(压缩BCD码）";
CM_ SG_ 2332157241 I2A_Byrack_Barcode2 "当前IMM的Barcode2(压缩BCD码）";
CM_ SG_ 2332157241 I2A_Byrack_Barcode3 "当前IMM的Barcode3(压缩BCD码）";
CM_ SG_ 2332157241 I2A_Byrack_Barcode4 "当前IMM的Barcode4(压缩BCD码）";
CM_ SG_ 2332157241 I2A_Byrack_Barcode5 "当前IMM的Barcode5(压缩BCD码）";
CM_ SG_ 2332157241 I2A_Byrack_Barcode6 "当前IMM的Barcode6(压缩BCD码）";
CM_ SG_ 2332157242 I2A_Byrack_Barcode1 "当前IMM的Barcode1(压缩BCD码）";
CM_ SG_ 2332157242 I2A_Byrack_Barcode2 "当前IMM的Barcode2(压缩BCD码）";
CM_ SG_ 2332157242 I2A_Byrack_Barcode3 "当前IMM的Barcode3(压缩BCD码）";
CM_ SG_ 2332157242 I2A_Byrack_Barcode4 "当前IMM的Barcode4(压缩BCD码）";
CM_ SG_ 2332157242 I2A_Byrack_Barcode5 "当前IMM的Barcode5(压缩BCD码）";
CM_ SG_ 2332157242 I2A_Byrack_Barcode6 "当前IMM的Barcode6(压缩BCD码）";
CM_ SG_ 2332157243 I2A_Byrack_Barcode1 "当前IMM的Barcode1(压缩BCD码）";
CM_ SG_ 2332157243 I2A_Byrack_Barcode2 "当前IMM的Barcode2(压缩BCD码）";
CM_ SG_ 2332157243 I2A_Byrack_Barcode3 "当前IMM的Barcode3(压缩BCD码）";
CM_ SG_ 2332157243 I2A_Byrack_Barcode4 "当前IMM的Barcode4(压缩BCD码）";
CM_ SG_ 2332157243 I2A_Byrack_Barcode5 "当前IMM的Barcode5(压缩BCD码）";
CM_ SG_ 2332157243 I2A_Byrack_Barcode6 "当前IMM的Barcode6(压缩BCD码）";
CM_ SG_ 2332157244 I2A_Byrack_Barcode1 "当前IMM的Barcode1(压缩BCD码）";
CM_ SG_ 2332157244 I2A_Byrack_Barcode2 "当前IMM的Barcode2(压缩BCD码）";
CM_ SG_ 2332157244 I2A_Byrack_Barcode3 "当前IMM的Barcode3(压缩BCD码）";
CM_ SG_ 2332157244 I2A_Byrack_Barcode4 "当前IMM的Barcode4(压缩BCD码）";
CM_ SG_ 2332157244 I2A_Byrack_Barcode5 "当前IMM的Barcode5(压缩BCD码）";
CM_ SG_ 2332157244 I2A_Byrack_Barcode6 "当前IMM的Barcode6(压缩BCD码）";
CM_ SG_ 2332157245 I2A_Byrack_Barcode1 "当前IMM的Barcode1(压缩BCD码）";
CM_ SG_ 2332157245 I2A_Byrack_Barcode2 "当前IMM的Barcode2(压缩BCD码）";
CM_ SG_ 2332157245 I2A_Byrack_Barcode3 "当前IMM的Barcode3(压缩BCD码）";
CM_ SG_ 2332157245 I2A_Byrack_Barcode4 "当前IMM的Barcode4(压缩BCD码）";
CM_ SG_ 2332157245 I2A_Byrack_Barcode5 "当前IMM的Barcode5(压缩BCD码）";
CM_ SG_ 2332157245 I2A_Byrack_Barcode6 "当前IMM的Barcode6(压缩BCD码）";
CM_ SG_ 2332157246 I2A_Byrack_Barcode1 "当前IMM的Barcode1(压缩BCD码）";
CM_ SG_ 2332157246 I2A_Byrack_Barcode2 "当前IMM的Barcode2(压缩BCD码）";
CM_ SG_ 2332157246 I2A_Byrack_Barcode3 "当前IMM的Barcode3(压缩BCD码）";
CM_ SG_ 2332157246 I2A_Byrack_Barcode4 "当前IMM的Barcode4(压缩BCD码）";
CM_ SG_ 2332157246 I2A_Byrack_Barcode5 "当前IMM的Barcode5(压缩BCD码）";
CM_ SG_ 2332157246 I2A_Byrack_Barcode6 "当前IMM的Barcode6(压缩BCD码）";
CM_ SG_ 2332157247 I2A_Byrack_Barcode1 "当前IMM的Barcode1(压缩BCD码）";
CM_ SG_ 2332157247 I2A_Byrack_Barcode2 "当前IMM的Barcode2(压缩BCD码）";
CM_ SG_ 2332157247 I2A_Byrack_Barcode3 "当前IMM的Barcode3(压缩BCD码）";
CM_ SG_ 2332157247 I2A_Byrack_Barcode4 "当前IMM的Barcode4(压缩BCD码）";
CM_ SG_ 2332157247 I2A_Byrack_Barcode5 "当前IMM的Barcode5(压缩BCD码）";
CM_ SG_ 2332157247 I2A_Byrack_Barcode6 "当前IMM的Barcode6(压缩BCD码）";
CM_ SG_ 2333535889 M2P_Measure_Vol_B1_01 "汇流排1所有高压在线电柜外侧电压平均值    ";
CM_ SG_ 2333535889 M2P_Current_B1_01 "汇流排1所有电柜电流累加和";
CM_ SG_ 2333535889 M2P_PermitMaxCharge_I_B1_01 "汇流排1最大允许充电电流";
CM_ SG_ 2333535889 M2P_PermitMaxDisCharge_I_B1_01 "汇流排1最大允许放电电流";
CM_ SG_ 2333535890 M2P_Measure_Vol_B1_02 "汇流排1所有高压在线电柜外侧电压平均值    ";
CM_ SG_ 2333535890 M2P_Current_B1_02 "汇流排1所有电柜电流累加和";
CM_ SG_ 2333535890 M2P_PermitMaxCharge_I_B1_02 "汇流排1最大允许充电电流";
CM_ SG_ 2333535890 M2P_PermitMaxDisCharge_I_B1_02 "汇流排1最大允许放电电流";
CM_ SG_ 2333535891 M2P_Measure_Vol_B1_03 "汇流排1所有高压在线电柜外侧电压平均值    ";
CM_ SG_ 2333535891 M2P_Current_B1_03 "汇流排1所有电柜电流累加和";
CM_ SG_ 2333535891 M2P_PermitMaxCharge_I_B1_03 "汇流排1最大允许充电电流";
CM_ SG_ 2333535891 M2P_PermitMaxDisCharge_I_B1_03 "汇流排1最大允许放电电流";
CM_ SG_ 2333535892 M2P_Measure_Vol_B1_04 "汇流排1所有高压在线电柜外侧电压平均值    ";
CM_ SG_ 2333535892 M2P_Current_B1_04 "汇流排1所有电柜电流累加和";
CM_ SG_ 2333535892 M2P_PermitMaxCharge_I_B1_04 "汇流排1最大允许充电电流";
CM_ SG_ 2333535892 M2P_PermitMaxDisCharge_I_B1_04 "汇流排1最大允许放电电流";
CM_ SG_ 2333535893 M2P_Measure_Vol_B1_05 "汇流排1所有高压在线电柜外侧电压平均值    ";
CM_ SG_ 2333535893 M2P_Current_B1_05 "汇流排1所有电柜电流累加和";
CM_ SG_ 2333535893 M2P_PermitMaxCharge_I_B1_05 "汇流排1最大允许充电电流";
CM_ SG_ 2333535893 M2P_PermitMaxDisCharge_I_B1_05 "汇流排1最大允许放电电流";
CM_ SG_ 2333535894 M2P_Measure_Vol_B1_06 "汇流排1所有高压在线电柜外侧电压平均值    ";
CM_ SG_ 2333535894 M2P_Current_B1_06 "汇流排1所有电柜电流累加和";
CM_ SG_ 2333535894 M2P_PermitMaxCharge_I_B1_06 "汇流排1最大允许充电电流";
CM_ SG_ 2333535894 M2P_PermitMaxDisCharge_I_B1_06 "汇流排1最大允许放电电流";
CM_ SG_ 2333535895 M2P_Measure_Vol_B1_07 "汇流排1所有高压在线电柜外侧电压平均值    ";
CM_ SG_ 2333535895 M2P_Current_B1_07 "汇流排1所有电柜电流累加和";
CM_ SG_ 2333535895 M2P_PermitMaxCharge_I_B1_07 "汇流排1最大允许充电电流";
CM_ SG_ 2333535895 M2P_PermitMaxDisCharge_I_B1_07 "汇流排1最大允许放电电流";
CM_ SG_ 2333535896 M2P_Measure_Vol_B1_08 "汇流排1所有高压在线电柜外侧电压平均值    ";
CM_ SG_ 2333535896 M2P_Current_B1_08 "汇流排1所有电柜电流累加和";
CM_ SG_ 2333535896 M2P_PermitMaxCharge_I_B1_08 "汇流排1最大允许充电电流";
CM_ SG_ 2333535896 M2P_PermitMaxDisCharge_I_B1_08 "汇流排1最大允许放电电流";
CM_ SG_ 2333535897 M2P_Measure_Vol_B1_09 "汇流排1所有高压在线电柜外侧电压平均值    ";
CM_ SG_ 2333535897 M2P_Current_B1_09 "汇流排1所有电柜电流累加和";
CM_ SG_ 2333535897 M2P_PermitMaxCharge_I_B1_09 "汇流排1最大允许充电电流";
CM_ SG_ 2333535897 M2P_PermitMaxDisCharge_I_B1_09 "汇流排1最大允许放电电流";
CM_ SG_ 2333535898 M2P_Measure_Vol_B1_10 "汇流排1所有高压在线电柜外侧电压平均值    ";
CM_ SG_ 2333535898 M2P_Current_B1_10 "汇流排1所有电柜电流累加和";
CM_ SG_ 2333535898 M2P_PermitMaxCharge_I_B1_10 "汇流排1最大允许充电电流";
CM_ SG_ 2333535898 M2P_PermitMaxDisCharge_I_B1_10 "汇流排1最大允许放电电流";
CM_ SG_ 2333535899 M2P_Measure_Vol_B1_11 "汇流排1所有高压在线电柜外侧电压平均值    ";
CM_ SG_ 2333535899 M2P_Current_B1_11 "汇流排1所有电柜电流累加和";
CM_ SG_ 2333535899 M2P_PermitMaxCharge_I_B1_11 "汇流排1最大允许充电电流";
CM_ SG_ 2333535899 M2P_PermitMaxDisCharge_I_B1_11 "汇流排1最大允许放电电流";
CM_ SG_ 2333535900 M2P_Measure_Vol_B1_12 "汇流排1所有高压在线电柜外侧电压平均值    ";
CM_ SG_ 2333535900 M2P_Current_B1_12 "汇流排1所有电柜电流累加和";
CM_ SG_ 2333535900 M2P_PermitMaxCharge_I_B1_12 "汇流排1最大允许充电电流";
CM_ SG_ 2333535900 M2P_PermitMaxDisCharge_I_B1_12 "汇流排1最大允许放电电流";
CM_ SG_ 2333535901 M2P_Measure_Vol_B1_13 "汇流排1所有高压在线电柜外侧电压平均值    ";
CM_ SG_ 2333535901 M2P_Current_B1_13 "汇流排1所有电柜电流累加和";
CM_ SG_ 2333535901 M2P_PermitMaxCharge_I_B1_13 "汇流排1最大允许充电电流";
CM_ SG_ 2333535901 M2P_PermitMaxDisCharge_I_B1_13 "汇流排1最大允许放电电流";
CM_ SG_ 2333535902 M2P_Measure_Vol_B1_14 "汇流排1所有高压在线电柜外侧电压平均值    ";
CM_ SG_ 2333535902 M2P_Current_B1_14 "汇流排1所有电柜电流累加和";
CM_ SG_ 2333535902 M2P_PermitMaxCharge_I_B1_14 "汇流排1最大允许充电电流";
CM_ SG_ 2333535902 M2P_PermitMaxDisCharge_I_B1_14 "汇流排1最大允许放电电流";
CM_ SG_ 2333535903 M2P_Measure_Vol_B1_15 "汇流排1所有高压在线电柜外侧电压平均值    ";
CM_ SG_ 2333535903 M2P_Current_B1_15 "汇流排1所有电柜电流累加和";
CM_ SG_ 2333535903 M2P_PermitMaxCharge_I_B1_15 "汇流排1最大允许充电电流";
CM_ SG_ 2333535903 M2P_PermitMaxDisCharge_I_B1_15 "汇流排1最大允许放电电流";
CM_ SG_ 2333535904 M2P_Measure_Vol_B1_16 "汇流排1所有高压在线电柜外侧电压平均值    ";
CM_ SG_ 2333535904 M2P_Current_B1_16 "汇流排1所有电柜电流累加和";
CM_ SG_ 2333535904 M2P_PermitMaxCharge_I_B1_16 "汇流排1最大允许充电电流";
CM_ SG_ 2333535904 M2P_PermitMaxDisCharge_I_B1_16 "汇流排1最大允许放电电流";
CM_ SG_ 2333535905 M2P_Measure_Vol_B1_17 "汇流排1所有高压在线电柜外侧电压平均值    ";
CM_ SG_ 2333535905 M2P_Current_B1_17 "汇流排1所有电柜电流累加和";
CM_ SG_ 2333535905 M2P_PermitMaxCharge_I_B1_17 "汇流排1最大允许充电电流";
CM_ SG_ 2333535905 M2P_PermitMaxDisCharge_I_B1_17 "汇流排1最大允许放电电流";
CM_ SG_ 2333535906 M2P_Measure_Vol_B1_18 "汇流排1所有高压在线电柜外侧电压平均值    ";
CM_ SG_ 2333535906 M2P_Current_B1_18 "汇流排1所有电柜电流累加和";
CM_ SG_ 2333535906 M2P_PermitMaxCharge_I_B1_18 "汇流排1最大允许充电电流";
CM_ SG_ 2333535906 M2P_PermitMaxDisCharge_I_B1_18 "汇流排1最大允许放电电流";
CM_ SG_ 2333535907 M2P_Measure_Vol_B1_19 "汇流排1所有高压在线电柜外侧电压平均值    ";
CM_ SG_ 2333535907 M2P_Current_B1_19 "汇流排1所有电柜电流累加和";
CM_ SG_ 2333535907 M2P_PermitMaxCharge_I_B1_19 "汇流排1最大允许充电电流";
CM_ SG_ 2333535907 M2P_PermitMaxDisCharge_I_B1_19 "汇流排1最大允许放电电流";
CM_ SG_ 2333535908 M2P_Measure_Vol_B1_20 "汇流排1所有高压在线电柜外侧电压平均值    ";
CM_ SG_ 2333535908 M2P_Current_B1_20 "汇流排1所有电柜电流累加和";
CM_ SG_ 2333535908 M2P_PermitMaxCharge_I_B1_20 "汇流排1最大允许充电电流";
CM_ SG_ 2333535908 M2P_PermitMaxDisCharge_I_B1_20 "汇流排1最大允许放电电流";
CM_ SG_ 2333535909 M2P_Measure_Vol_B1_21 "汇流排1所有高压在线电柜外侧电压平均值    ";
CM_ SG_ 2333535909 M2P_Current_B1_21 "汇流排1所有电柜电流累加和";
CM_ SG_ 2333535909 M2P_PermitMaxCharge_I_B1_21 "汇流排1最大允许充电电流";
CM_ SG_ 2333535909 M2P_PermitMaxDisCharge_I_B1_21 "汇流排1最大允许放电电流";
CM_ SG_ 2333535910 M2P_Measure_Vol_B1_22 "汇流排1所有高压在线电柜外侧电压平均值    ";
CM_ SG_ 2333535910 M2P_Current_B1_22 "汇流排1所有电柜电流累加和";
CM_ SG_ 2333535910 M2P_PermitMaxCharge_I_B1_22 "汇流排1最大允许充电电流";
CM_ SG_ 2333535910 M2P_PermitMaxDisCharge_I_B1_22 "汇流排1最大允许放电电流";
CM_ SG_ 2333535911 M2P_Measure_Vol_B1_23 "汇流排1所有高压在线电柜外侧电压平均值    ";
CM_ SG_ 2333535911 M2P_Current_B1_23 "汇流排1所有电柜电流累加和";
CM_ SG_ 2333535911 M2P_PermitMaxCharge_I_B1_23 "汇流排1最大允许充电电流";
CM_ SG_ 2333535911 M2P_PermitMaxDisCharge_I_B1_23 "汇流排1最大允许放电电流";
CM_ SG_ 2333535912 M2P_Measure_Vol_B1_24 "汇流排1所有高压在线电柜外侧电压平均值    ";
CM_ SG_ 2333535912 M2P_Current_B1_24 "汇流排1所有电柜电流累加和";
CM_ SG_ 2333535912 M2P_PermitMaxCharge_I_B1_24 "汇流排1最大允许充电电流";
CM_ SG_ 2333535912 M2P_PermitMaxDisCharge_I_B1_24 "汇流排1最大允许放电电流";
CM_ SG_ 2333535913 M2P_Measure_Vol_B1_25 "汇流排1所有高压在线电柜外侧电压平均值    ";
CM_ SG_ 2333535913 M2P_Current_B1_25 "汇流排1所有电柜电流累加和";
CM_ SG_ 2333535913 M2P_PermitMaxCharge_I_B1_25 "汇流排1最大允许充电电流";
CM_ SG_ 2333535913 M2P_PermitMaxDisCharge_I_B1_25 "汇流排1最大允许放电电流";
CM_ SG_ 2333535914 M2P_Measure_Vol_B1_26 "汇流排1所有高压在线电柜外侧电压平均值    ";
CM_ SG_ 2333535914 M2P_Current_B1_26 "汇流排1所有电柜电流累加和";
CM_ SG_ 2333535914 M2P_PermitMaxCharge_I_B1_26 "汇流排1最大允许充电电流";
CM_ SG_ 2333535914 M2P_PermitMaxDisCharge_I_B1_26 "汇流排1最大允许放电电流";
CM_ SG_ 2333535915 M2P_Measure_Vol_B1_27 "汇流排1所有高压在线电柜外侧电压平均值    ";
CM_ SG_ 2333535915 M2P_Current_B1_27 "汇流排1所有电柜电流累加和";
CM_ SG_ 2333535915 M2P_PermitMaxCharge_I_B1_27 "汇流排1最大允许充电电流";
CM_ SG_ 2333535915 M2P_PermitMaxDisCharge_I_B1_27 "汇流排1最大允许放电电流";
CM_ SG_ 2333535916 M2P_Measure_Vol_B1_28 "汇流排1所有高压在线电柜外侧电压平均值    ";
CM_ SG_ 2333535916 M2P_Current_B1_28 "汇流排1所有电柜电流累加和";
CM_ SG_ 2333535916 M2P_PermitMaxCharge_I_B1_28 "汇流排1最大允许充电电流";
CM_ SG_ 2333535916 M2P_PermitMaxDisCharge_I_B1_28 "汇流排1最大允许放电电流";
VAL_ 2333077148 Reserved_12 0 "正常" 1 "故障" ;
VAL_ 2333077149 Reserved_13 0 "正常" 1 "故障" ;
VAL_ 2333077150 Reserved_14 0 "正常" 1 "故障" ;
VAL_ 2333077151 Reserved_15 0 "正常" 1 "故障" ;
VAL_ 2333077152 Reserved_16 0 "正常" 1 "故障" ;
VAL_ 2333077153 Reserved_17 0 "正常" 1 "故障" ;
VAL_ 2333077154 Reserved_18 0 "正常" 1 "故障" ;
VAL_ 2333077155 Reserved_19 0 "正常" 1 "故障" ;
VAL_ 2333077156 Reserved_20 0 "正常" 1 "故障" ;
VAL_ 2333077157 Reserved_21 0 "正常" 1 "故障" ;
VAL_ 2333077158 Reserved_22 0 "正常" 1 "故障" ;
VAL_ 2333077159 Reserved_23 0 "正常" 1 "故障" ;
VAL_ 2333077160 Reserved_24 0 "正常" 1 "故障" ;
VAL_ 2333077161 Reserved_25 0 "正常" 1 "故障" ;
VAL_ 2333077162 Reserved_26 0 "正常" 1 "故障" ;
VAL_ 2333077163 Reserved_27 0 "正常" 1 "故障" ;
VAL_ 2333077164 Reserved_28 0 "正常" 1 "故障" ;
VAL_ 2333077165 Reserved_29 0 "正常" 1 "故障" ;
VAL_ 2333077166 Reserved_30 0 "正常" 1 "故障" ;
VAL_ 2333077167 Reserved_31 0 "正常" 1 "故障" ;
VAL_ 2333535889 M2P_Measure_Vol_B1_01 65535 "Invalid" ;
VAL_ 2333535889 M2P_Current_B1_01 65535 "Invalid" ;
VAL_ 2333535889 M2P_PermitMaxCharge_I_B1_01 65535 "Invalid" ;
VAL_ 2333535889 M2P_PermitMaxDisCharge_I_B1_01 65535 "Invalid" ;
VAL_ 2333535890 M2P_Measure_Vol_B1_02 65535 "Invalid" ;
VAL_ 2333535890 M2P_Current_B1_02 65535 "Invalid" ;
VAL_ 2333535890 M2P_PermitMaxCharge_I_B1_02 65535 "Invalid" ;
VAL_ 2333535890 M2P_PermitMaxDisCharge_I_B1_02 65535 "Invalid" ;
VAL_ 2333535891 M2P_Measure_Vol_B1_03 65535 "Invalid" ;
VAL_ 2333535891 M2P_Current_B1_03 65535 "Invalid" ;
VAL_ 2333535891 M2P_PermitMaxCharge_I_B1_03 65535 "Invalid" ;
VAL_ 2333535891 M2P_PermitMaxDisCharge_I_B1_03 65535 "Invalid" ;
VAL_ 2333535892 M2P_Measure_Vol_B1_04 65535 "Invalid" ;
VAL_ 2333535892 M2P_Current_B1_04 65535 "Invalid" ;
VAL_ 2333535892 M2P_PermitMaxCharge_I_B1_04 65535 "Invalid" ;
VAL_ 2333535892 M2P_PermitMaxDisCharge_I_B1_04 65535 "Invalid" ;
VAL_ 2333535893 M2P_Measure_Vol_B1_05 65535 "Invalid" ;
VAL_ 2333535893 M2P_Current_B1_05 65535 "Invalid" ;
VAL_ 2333535893 M2P_PermitMaxCharge_I_B1_05 65535 "Invalid" ;
VAL_ 2333535893 M2P_PermitMaxDisCharge_I_B1_05 65535 "Invalid" ;
VAL_ 2333535894 M2P_Measure_Vol_B1_06 65535 "Invalid" ;
VAL_ 2333535894 M2P_Current_B1_06 65535 "Invalid" ;
VAL_ 2333535894 M2P_PermitMaxCharge_I_B1_06 65535 "Invalid" ;
VAL_ 2333535894 M2P_PermitMaxDisCharge_I_B1_06 65535 "Invalid" ;
VAL_ 2333535895 M2P_Measure_Vol_B1_07 65535 "Invalid" ;
VAL_ 2333535895 M2P_Current_B1_07 65535 "Invalid" ;
VAL_ 2333535895 M2P_PermitMaxCharge_I_B1_07 65535 "Invalid" ;
VAL_ 2333535895 M2P_PermitMaxDisCharge_I_B1_07 65535 "Invalid" ;
VAL_ 2333535896 M2P_Measure_Vol_B1_08 65535 "Invalid" ;
VAL_ 2333535896 M2P_Current_B1_08 65535 "Invalid" ;
VAL_ 2333535896 M2P_PermitMaxCharge_I_B1_08 65535 "Invalid" ;
VAL_ 2333535896 M2P_PermitMaxDisCharge_I_B1_08 65535 "Invalid" ;
VAL_ 2333535897 M2P_Measure_Vol_B1_09 65535 "Invalid" ;
VAL_ 2333535897 M2P_Current_B1_09 65535 "Invalid" ;
VAL_ 2333535897 M2P_PermitMaxCharge_I_B1_09 65535 "Invalid" ;
VAL_ 2333535897 M2P_PermitMaxDisCharge_I_B1_09 65535 "Invalid" ;
VAL_ 2333535898 M2P_Measure_Vol_B1_10 65535 "Invalid" ;
VAL_ 2333535898 M2P_Current_B1_10 65535 "Invalid" ;
VAL_ 2333535898 M2P_PermitMaxCharge_I_B1_10 65535 "Invalid" ;
VAL_ 2333535898 M2P_PermitMaxDisCharge_I_B1_10 65535 "Invalid" ;
VAL_ 2333535899 M2P_Measure_Vol_B1_11 65535 "Invalid" ;
VAL_ 2333535899 M2P_Current_B1_11 65535 "Invalid" ;
VAL_ 2333535899 M2P_PermitMaxCharge_I_B1_11 65535 "Invalid" ;
VAL_ 2333535899 M2P_PermitMaxDisCharge_I_B1_11 65535 "Invalid" ;
VAL_ 2333535900 M2P_Measure_Vol_B1_12 65535 "Invalid" ;
VAL_ 2333535900 M2P_Current_B1_12 65535 "Invalid" ;
VAL_ 2333535900 M2P_PermitMaxCharge_I_B1_12 65535 "Invalid" ;
VAL_ 2333535900 M2P_PermitMaxDisCharge_I_B1_12 65535 "Invalid" ;
VAL_ 2333535901 M2P_Measure_Vol_B1_13 65535 "Invalid" ;
VAL_ 2333535901 M2P_Current_B1_13 65535 "Invalid" ;
VAL_ 2333535901 M2P_PermitMaxCharge_I_B1_13 65535 "Invalid" ;
VAL_ 2333535901 M2P_PermitMaxDisCharge_I_B1_13 65535 "Invalid" ;
VAL_ 2333535902 M2P_Measure_Vol_B1_14 65535 "Invalid" ;
VAL_ 2333535902 M2P_Current_B1_14 65535 "Invalid" ;
VAL_ 2333535902 M2P_PermitMaxCharge_I_B1_14 65535 "Invalid" ;
VAL_ 2333535902 M2P_PermitMaxDisCharge_I_B1_14 65535 "Invalid" ;
VAL_ 2333535903 M2P_Measure_Vol_B1_15 65535 "Invalid" ;
VAL_ 2333535903 M2P_Current_B1_15 65535 "Invalid" ;
VAL_ 2333535903 M2P_PermitMaxCharge_I_B1_15 65535 "Invalid" ;
VAL_ 2333535903 M2P_PermitMaxDisCharge_I_B1_15 65535 "Invalid" ;
VAL_ 2333535904 M2P_Measure_Vol_B1_16 65535 "Invalid" ;
VAL_ 2333535904 M2P_Current_B1_16 65535 "Invalid" ;
VAL_ 2333535904 M2P_PermitMaxCharge_I_B1_16 65535 "Invalid" ;
VAL_ 2333535904 M2P_PermitMaxDisCharge_I_B1_16 65535 "Invalid" ;
VAL_ 2333535905 M2P_Measure_Vol_B1_17 65535 "Invalid" ;
VAL_ 2333535905 M2P_Current_B1_17 65535 "Invalid" ;
VAL_ 2333535905 M2P_PermitMaxCharge_I_B1_17 65535 "Invalid" ;
VAL_ 2333535905 M2P_PermitMaxDisCharge_I_B1_17 65535 "Invalid" ;
VAL_ 2333535906 M2P_Measure_Vol_B1_18 65535 "Invalid" ;
VAL_ 2333535906 M2P_Current_B1_18 65535 "Invalid" ;
VAL_ 2333535906 M2P_PermitMaxCharge_I_B1_18 65535 "Invalid" ;
VAL_ 2333535906 M2P_PermitMaxDisCharge_I_B1_18 65535 "Invalid" ;
VAL_ 2333535907 M2P_Measure_Vol_B1_19 65535 "Invalid" ;
VAL_ 2333535907 M2P_Current_B1_19 65535 "Invalid" ;
VAL_ 2333535907 M2P_PermitMaxCharge_I_B1_19 65535 "Invalid" ;
VAL_ 2333535907 M2P_PermitMaxDisCharge_I_B1_19 65535 "Invalid" ;
VAL_ 2333535908 M2P_Measure_Vol_B1_20 65535 "Invalid" ;
VAL_ 2333535908 M2P_Current_B1_20 65535 "Invalid" ;
VAL_ 2333535908 M2P_PermitMaxCharge_I_B1_20 65535 "Invalid" ;
VAL_ 2333535908 M2P_PermitMaxDisCharge_I_B1_20 65535 "Invalid" ;
VAL_ 2333535909 M2P_Measure_Vol_B1_21 65535 "Invalid" ;
VAL_ 2333535909 M2P_Current_B1_21 65535 "Invalid" ;
VAL_ 2333535909 M2P_PermitMaxCharge_I_B1_21 65535 "Invalid" ;
VAL_ 2333535909 M2P_PermitMaxDisCharge_I_B1_21 65535 "Invalid" ;
VAL_ 2333535910 M2P_Measure_Vol_B1_22 65535 "Invalid" ;
VAL_ 2333535910 M2P_Current_B1_22 65535 "Invalid" ;
VAL_ 2333535910 M2P_PermitMaxCharge_I_B1_22 65535 "Invalid" ;
VAL_ 2333535910 M2P_PermitMaxDisCharge_I_B1_22 65535 "Invalid" ;
VAL_ 2333535911 M2P_Measure_Vol_B1_23 65535 "Invalid" ;
VAL_ 2333535911 M2P_Current_B1_23 65535 "Invalid" ;
VAL_ 2333535911 M2P_PermitMaxCharge_I_B1_23 65535 "Invalid" ;
VAL_ 2333535911 M2P_PermitMaxDisCharge_I_B1_23 65535 "Invalid" ;
VAL_ 2333535912 M2P_Measure_Vol_B1_24 65535 "Invalid" ;
VAL_ 2333535912 M2P_Current_B1_24 65535 "Invalid" ;
VAL_ 2333535912 M2P_PermitMaxCharge_I_B1_24 65535 "Invalid" ;
VAL_ 2333535912 M2P_PermitMaxDisCharge_I_B1_24 65535 "Invalid" ;
VAL_ 2333535913 M2P_Measure_Vol_B1_25 65535 "Invalid" ;
VAL_ 2333535913 M2P_Current_B1_25 65535 "Invalid" ;
VAL_ 2333535913 M2P_PermitMaxCharge_I_B1_25 65535 "Invalid" ;
VAL_ 2333535913 M2P_PermitMaxDisCharge_I_B1_25 65535 "Invalid" ;
VAL_ 2333535914 M2P_Measure_Vol_B1_26 65535 "Invalid" ;
VAL_ 2333535914 M2P_Current_B1_26 65535 "Invalid" ;
VAL_ 2333535914 M2P_PermitMaxCharge_I_B1_26 65535 "Invalid" ;
VAL_ 2333535914 M2P_PermitMaxDisCharge_I_B1_26 65535 "Invalid" ;
VAL_ 2333535915 M2P_Measure_Vol_B1_27 65535 "Invalid" ;
VAL_ 2333535915 M2P_Current_B1_27 65535 "Invalid" ;
VAL_ 2333535915 M2P_PermitMaxCharge_I_B1_27 65535 "Invalid" ;
VAL_ 2333535915 M2P_PermitMaxDisCharge_I_B1_27 65535 "Invalid" ;
VAL_ 2333535916 M2P_Measure_Vol_B1_28 65535 "Invalid" ;
VAL_ 2333535916 M2P_Current_B1_28 65535 "Invalid" ;
VAL_ 2333535916 M2P_PermitMaxCharge_I_B1_28 65535 "Invalid" ;
VAL_ 2333535916 M2P_PermitMaxDisCharge_I_B1_28 65535 "Invalid" ;
VERSION ""

NS_ :

BS_:

BU_: MBMU PC SBMU IMM ETH DCDC LEMS

BO_ 2333535917 M2P_SUMDATA15__29: 8 MBMU
 SG_ M2P_Measure_Vol_B1_29 : 0|16@1+ (0.1,0) [0|6553.5] "V"  PC,SBMU
 SG_ M2P_Current_B1_29 : 16|16@1+ (1,-20000) [-20000|45535] "A"  PC,SBMU
 SG_ M2P_PermitMaxCharge_I_B1_29 : 32|16@1+ (1,-20000) [-20000|45535] "A"  PC
 SG_ M2P_PermitMaxDisCharge_I_B1_29 : 48|16@1+ (1,-20000) [-20000|45535] "A"  PC

BO_ 2333535918 M2P_SUMDATA15__30: 8 MBMU
 SG_ M2P_Measure_Vol_B1_30 : 0|16@1+ (0.1,0) [0|6553.5] "V"  PC,SBMU
 SG_ M2P_Current_B1_30 : 16|16@1+ (1,-20000) [-20000|45535] "A"  PC,SBMU
 SG_ M2P_PermitMaxCharge_I_B1_30 : 32|16@1+ (1,-20000) [-20000|45535] "A"  PC
 SG_ M2P_PermitMaxDisCharge_I_B1_30 : 48|16@1+ (1,-20000) [-20000|45535] "A"  PC

BO_ 2333535919 M2P_SUMDATA15__31: 8 MBMU
 SG_ M2P_Measure_Vol_B1_31 : 0|16@1+ (0.1,0) [0|6553.5] "V"  PC,SBMU
 SG_ M2P_Current_B1_31 : 16|16@1+ (1,-20000) [-20000|45535] "A"  PC,SBMU
 SG_ M2P_PermitMaxCharge_I_B1_31 : 32|16@1+ (1,-20000) [-20000|45535] "A"  PC
 SG_ M2P_PermitMaxDisCharge_I_B1_31 : 48|16@1+ (1,-20000) [-20000|45535] "A"  PC

BO_ 2333601425 M2P_SUMDATA16__01: 8 MBMU
 SG_ M2P_PermitMaxVolt_B1_01 : 0|16@1+ (0.1,0) [0|6553.5] "V"  PC
 SG_ M2P_PermitMinVolt_B1_01 : 16|16@1+ (0.1,0) [0|6553.5] "V"  PC
 SG_ M2P_PermitMaxPow_Chg_B1_01 : 32|16@1+ (1,-20000) [-20000|45535] "Kw"  PC
 SG_ M2P_PermitMaxPow_DisChg_B1_01 : 48|16@1+ (1,-20000) [-20000|45535] "Kw"  PC

BO_ 2333601426 M2P_SUMDATA16__02: 8 MBMU
 SG_ M2P_PermitMaxVolt_B1_02 : 0|16@1+ (0.1,0) [0|6553.5] "V"  PC
 SG_ M2P_PermitMinVolt_B1_02 : 16|16@1+ (0.1,0) [0|6553.5] "V"  PC
 SG_ M2P_PermitMaxPow_Chg_B1_02 : 32|16@1+ (1,-20000) [-20000|45535] "Kw"  PC
 SG_ M2P_PermitMaxPow_DisChg_B1_02 : 48|16@1+ (1,-20000) [-20000|45535] "Kw"  PC

BO_ 2333601427 M2P_SUMDATA16__03: 8 MBMU
 SG_ M2P_PermitMaxVolt_B1_03 : 0|16@1+ (0.1,0) [0|6553.5] "V"  PC
 SG_ M2P_PermitMinVolt_B1_03 : 16|16@1+ (0.1,0) [0|6553.5] "V"  PC
 SG_ M2P_PermitMaxPow_Chg_B1_03 : 32|16@1+ (1,-20000) [-20000|45535] "Kw"  PC
 SG_ M2P_PermitMaxPow_DisChg_B1_03 : 48|16@1+ (1,-20000) [-20000|45535] "Kw"  PC

BO_ 2333601428 M2P_SUMDATA16__04: 8 MBMU
 SG_ M2P_PermitMaxVolt_B1_04 : 0|16@1+ (0.1,0) [0|6553.5] "V"  PC
 SG_ M2P_PermitMinVolt_B1_04 : 16|16@1+ (0.1,0) [0|6553.5] "V"  PC
 SG_ M2P_PermitMaxPow_Chg_B1_04 : 32|16@1+ (1,-20000) [-20000|45535] "Kw"  PC
 SG_ M2P_PermitMaxPow_DisChg_B1_04 : 48|16@1+ (1,-20000) [-20000|45535] "Kw"  PC

BO_ 2333601429 M2P_SUMDATA16__05: 8 MBMU
 SG_ M2P_PermitMaxVolt_B1_05 : 0|16@1+ (0.1,0) [0|6553.5] "V"  PC
 SG_ M2P_PermitMinVolt_B1_05 : 16|16@1+ (0.1,0) [0|6553.5] "V"  PC
 SG_ M2P_PermitMaxPow_Chg_B1_05 : 32|16@1+ (1,-20000) [-20000|45535] "Kw"  PC
 SG_ M2P_PermitMaxPow_DisChg_B1_05 : 48|16@1+ (1,-20000) [-20000|45535] "Kw"  PC

BO_ 2333601430 M2P_SUMDATA16__06: 8 MBMU
 SG_ M2P_PermitMaxVolt_B1_06 : 0|16@1+ (0.1,0) [0|6553.5] "V"  PC
 SG_ M2P_PermitMinVolt_B1_06 : 16|16@1+ (0.1,0) [0|6553.5] "V"  PC
 SG_ M2P_PermitMaxPow_Chg_B1_06 : 32|16@1+ (1,-20000) [-20000|45535] "Kw"  PC
 SG_ M2P_PermitMaxPow_DisChg_B1_06 : 48|16@1+ (1,-20000) [-20000|45535] "Kw"  PC

BO_ 2333601431 M2P_SUMDATA16__07: 8 MBMU
 SG_ M2P_PermitMaxVolt_B1_07 : 0|16@1+ (0.1,0) [0|6553.5] "V"  PC
 SG_ M2P_PermitMinVolt_B1_07 : 16|16@1+ (0.1,0) [0|6553.5] "V"  PC
 SG_ M2P_PermitMaxPow_Chg_B1_07 : 32|16@1+ (1,-20000) [-20000|45535] "Kw"  PC
 SG_ M2P_PermitMaxPow_DisChg_B1_07 : 48|16@1+ (1,-20000) [-20000|45535] "Kw"  PC

BO_ 2333601432 M2P_SUMDATA16__08: 8 MBMU
 SG_ M2P_PermitMaxVolt_B1_08 : 0|16@1+ (0.1,0) [0|6553.5] "V"  PC
 SG_ M2P_PermitMinVolt_B1_08 : 16|16@1+ (0.1,0) [0|6553.5] "V"  PC
 SG_ M2P_PermitMaxPow_Chg_B1_08 : 32|16@1+ (1,-20000) [-20000|45535] "Kw"  PC
 SG_ M2P_PermitMaxPow_DisChg_B1_08 : 48|16@1+ (1,-20000) [-20000|45535] "Kw"  PC

BO_ 2333601433 M2P_SUMDATA16__09: 8 MBMU
 SG_ M2P_PermitMaxVolt_B1_09 : 0|16@1+ (0.1,0) [0|6553.5] "V"  PC
 SG_ M2P_PermitMinVolt_B1_09 : 16|16@1+ (0.1,0) [0|6553.5] "V"  PC
 SG_ M2P_PermitMaxPow_Chg_B1_09 : 32|16@1+ (1,-20000) [-20000|45535] "Kw"  PC
 SG_ M2P_PermitMaxPow_DisChg_B1_09 : 48|16@1+ (1,-20000) [-20000|45535] "Kw"  PC

BO_ 2333601434 M2P_SUMDATA16__10: 8 MBMU
 SG_ M2P_PermitMaxVolt_B1_10 : 0|16@1+ (0.1,0) [0|6553.5] "V"  PC
 SG_ M2P_PermitMinVolt_B1_10 : 16|16@1+ (0.1,0) [0|6553.5] "V"  PC
 SG_ M2P_PermitMaxPow_Chg_B1_10 : 32|16@1+ (1,-20000) [-20000|45535] "Kw"  PC
 SG_ M2P_PermitMaxPow_DisChg_B1_10 : 48|16@1+ (1,-20000) [-20000|45535] "Kw"  PC

BO_ 2333601435 M2P_SUMDATA16__11: 8 MBMU
 SG_ M2P_PermitMaxVolt_B1_11 : 0|16@1+ (0.1,0) [0|6553.5] "V"  PC
 SG_ M2P_PermitMinVolt_B1_11 : 16|16@1+ (0.1,0) [0|6553.5] "V"  PC
 SG_ M2P_PermitMaxPow_Chg_B1_11 : 32|16@1+ (1,-20000) [-20000|45535] "Kw"  PC
 SG_ M2P_PermitMaxPow_DisChg_B1_11 : 48|16@1+ (1,-20000) [-20000|45535] "Kw"  PC

BO_ 2333601436 M2P_SUMDATA16__12: 8 MBMU
 SG_ M2P_PermitMaxVolt_B1_12 : 0|16@1+ (0.1,0) [0|6553.5] "V"  PC
 SG_ M2P_PermitMinVolt_B1_12 : 16|16@1+ (0.1,0) [0|6553.5] "V"  PC
 SG_ M2P_PermitMaxPow_Chg_B1_12 : 32|16@1+ (1,-20000) [-20000|45535] "Kw"  PC
 SG_ M2P_PermitMaxPow_DisChg_B1_12 : 48|16@1+ (1,-20000) [-20000|45535] "Kw"  PC

BO_ 2333601437 M2P_SUMDATA16__13: 8 MBMU
 SG_ M2P_PermitMaxVolt_B1_13 : 0|16@1+ (0.1,0) [0|6553.5] "V"  PC
 SG_ M2P_PermitMinVolt_B1_13 : 16|16@1+ (0.1,0) [0|6553.5] "V"  PC
 SG_ M2P_PermitMaxPow_Chg_B1_13 : 32|16@1+ (1,-20000) [-20000|45535] "Kw"  PC
 SG_ M2P_PermitMaxPow_DisChg_B1_13 : 48|16@1+ (1,-20000) [-20000|45535] "Kw"  PC

BO_ 2333601438 M2P_SUMDATA16__14: 8 MBMU
 SG_ M2P_PermitMaxVolt_B1_14 : 0|16@1+ (0.1,0) [0|6553.5] "V"  PC
 SG_ M2P_PermitMinVolt_B1_14 : 16|16@1+ (0.1,0) [0|6553.5] "V"  PC
 SG_ M2P_PermitMaxPow_Chg_B1_14 : 32|16@1+ (1,-20000) [-20000|45535] "Kw"  PC
 SG_ M2P_PermitMaxPow_DisChg_B1_14 : 48|16@1+ (1,-20000) [-20000|45535] "Kw"  PC

BO_ 2333601439 M2P_SUMDATA16__15: 8 MBMU
 SG_ M2P_PermitMaxVolt_B1_15 : 0|16@1+ (0.1,0) [0|6553.5] "V"  PC
 SG_ M2P_PermitMinVolt_B1_15 : 16|16@1+ (0.1,0) [0|6553.5] "V"  PC
 SG_ M2P_PermitMaxPow_Chg_B1_15 : 32|16@1+ (1,-20000) [-20000|45535] "Kw"  PC
 SG_ M2P_PermitMaxPow_DisChg_B1_15 : 48|16@1+ (1,-20000) [-20000|45535] "Kw"  PC

BO_ 2333601440 M2P_SUMDATA16__16: 8 MBMU
 SG_ M2P_PermitMaxVolt_B1_16 : 0|16@1+ (0.1,0) [0|6553.5] "V"  PC
 SG_ M2P_PermitMinVolt_B1_16 : 16|16@1+ (0.1,0) [0|6553.5] "V"  PC
 SG_ M2P_PermitMaxPow_Chg_B1_16 : 32|16@1+ (1,-20000) [-20000|45535] "Kw"  PC
 SG_ M2P_PermitMaxPow_DisChg_B1_16 : 48|16@1+ (1,-20000) [-20000|45535] "Kw"  PC

BO_ 2333601441 M2P_SUMDATA16__17: 8 MBMU
 SG_ M2P_PermitMaxVolt_B1_17 : 0|16@1+ (0.1,0) [0|6553.5] "V"  PC
 SG_ M2P_PermitMinVolt_B1_17 : 16|16@1+ (0.1,0) [0|6553.5] "V"  PC
 SG_ M2P_PermitMaxPow_Chg_B1_17 : 32|16@1+ (1,-20000) [-20000|45535] "Kw"  PC
 SG_ M2P_PermitMaxPow_DisChg_B1_17 : 48|16@1+ (1,-20000) [-20000|45535] "Kw"  PC

BO_ 2333601442 M2P_SUMDATA16__18: 8 MBMU
 SG_ M2P_PermitMaxVolt_B1_18 : 0|16@1+ (0.1,0) [0|6553.5] "V"  PC
 SG_ M2P_PermitMinVolt_B1_18 : 16|16@1+ (0.1,0) [0|6553.5] "V"  PC
 SG_ M2P_PermitMaxPow_Chg_B1_18 : 32|16@1+ (1,-20000) [-20000|45535] "Kw"  PC
 SG_ M2P_PermitMaxPow_DisChg_B1_18 : 48|16@1+ (1,-20000) [-20000|45535] "Kw"  PC

BO_ 2333601443 M2P_SUMDATA16__19: 8 MBMU
 SG_ M2P_PermitMaxVolt_B1_19 : 0|16@1+ (0.1,0) [0|6553.5] "V"  PC
 SG_ M2P_PermitMinVolt_B1_19 : 16|16@1+ (0.1,0) [0|6553.5] "V"  PC
 SG_ M2P_PermitMaxPow_Chg_B1_19 : 32|16@1+ (1,-20000) [-20000|45535] "Kw"  PC
 SG_ M2P_PermitMaxPow_DisChg_B1_19 : 48|16@1+ (1,-20000) [-20000|45535] "Kw"  PC

BO_ 2333601444 M2P_SUMDATA16__20: 8 MBMU
 SG_ M2P_PermitMaxVolt_B1_20 : 0|16@1+ (0.1,0) [0|6553.5] "V"  PC
 SG_ M2P_PermitMinVolt_B1_20 : 16|16@1+ (0.1,0) [0|6553.5] "V"  PC
 SG_ M2P_PermitMaxPow_Chg_B1_20 : 32|16@1+ (1,-20000) [-20000|45535] "Kw"  PC
 SG_ M2P_PermitMaxPow_DisChg_B1_20 : 48|16@1+ (1,-20000) [-20000|45535] "Kw"  PC

BO_ 2333601445 M2P_SUMDATA16__21: 8 MBMU
 SG_ M2P_PermitMaxVolt_B1_21 : 0|16@1+ (0.1,0) [0|6553.5] "V"  PC
 SG_ M2P_PermitMinVolt_B1_21 : 16|16@1+ (0.1,0) [0|6553.5] "V"  PC
 SG_ M2P_PermitMaxPow_Chg_B1_21 : 32|16@1+ (1,-20000) [-20000|45535] "Kw"  PC
 SG_ M2P_PermitMaxPow_DisChg_B1_21 : 48|16@1+ (1,-20000) [-20000|45535] "Kw"  PC

BO_ 2333601446 M2P_SUMDATA16__22: 8 MBMU
 SG_ M2P_PermitMaxVolt_B1_22 : 0|16@1+ (0.1,0) [0|6553.5] "V"  PC
 SG_ M2P_PermitMinVolt_B1_22 : 16|16@1+ (0.1,0) [0|6553.5] "V"  PC
 SG_ M2P_PermitMaxPow_Chg_B1_22 : 32|16@1+ (1,-20000) [-20000|45535] "Kw"  PC
 SG_ M2P_PermitMaxPow_DisChg_B1_22 : 48|16@1+ (1,-20000) [-20000|45535] "Kw"  PC

BO_ 2333601447 M2P_SUMDATA16__23: 8 MBMU
 SG_ M2P_PermitMaxVolt_B1_23 : 0|16@1+ (0.1,0) [0|6553.5] "V"  PC
 SG_ M2P_PermitMinVolt_B1_23 : 16|16@1+ (0.1,0) [0|6553.5] "V"  PC
 SG_ M2P_PermitMaxPow_Chg_B1_23 : 32|16@1+ (1,-20000) [-20000|45535] "Kw"  PC
 SG_ M2P_PermitMaxPow_DisChg_B1_23 : 48|16@1+ (1,-20000) [-20000|45535] "Kw"  PC

BO_ 2333601448 M2P_SUMDATA16__24: 8 MBMU
 SG_ M2P_PermitMaxVolt_B1_24 : 0|16@1+ (0.1,0) [0|6553.5] "V"  PC
 SG_ M2P_PermitMinVolt_B1_24 : 16|16@1+ (0.1,0) [0|6553.5] "V"  PC
 SG_ M2P_PermitMaxPow_Chg_B1_24 : 32|16@1+ (1,-20000) [-20000|45535] "Kw"  PC
 SG_ M2P_PermitMaxPow_DisChg_B1_24 : 48|16@1+ (1,-20000) [-20000|45535] "Kw"  PC

BO_ 2333601449 M2P_SUMDATA16__25: 8 MBMU
 SG_ M2P_PermitMaxVolt_B1_25 : 0|16@1+ (0.1,0) [0|6553.5] "V"  PC
 SG_ M2P_PermitMinVolt_B1_25 : 16|16@1+ (0.1,0) [0|6553.5] "V"  PC
 SG_ M2P_PermitMaxPow_Chg_B1_25 : 32|16@1+ (1,-20000) [-20000|45535] "Kw"  PC
 SG_ M2P_PermitMaxPow_DisChg_B1_25 : 48|16@1+ (1,-20000) [-20000|45535] "Kw"  PC

BO_ 2333601450 M2P_SUMDATA16__26: 8 MBMU
 SG_ M2P_PermitMaxVolt_B1_26 : 0|16@1+ (0.1,0) [0|6553.5] "V"  PC
 SG_ M2P_PermitMinVolt_B1_26 : 16|16@1+ (0.1,0) [0|6553.5] "V"  PC
 SG_ M2P_PermitMaxPow_Chg_B1_26 : 32|16@1+ (1,-20000) [-20000|45535] "Kw"  PC
 SG_ M2P_PermitMaxPow_DisChg_B1_26 : 48|16@1+ (1,-20000) [-20000|45535] "Kw"  PC

BO_ 2333601451 M2P_SUMDATA16__27: 8 MBMU
 SG_ M2P_PermitMaxVolt_B1_27 : 0|16@1+ (0.1,0) [0|6553.5] "V"  PC
 SG_ M2P_PermitMinVolt_B1_27 : 16|16@1+ (0.1,0) [0|6553.5] "V"  PC
 SG_ M2P_PermitMaxPow_Chg_B1_27 : 32|16@1+ (1,-20000) [-20000|45535] "Kw"  PC
 SG_ M2P_PermitMaxPow_DisChg_B1_27 : 48|16@1+ (1,-20000) [-20000|45535] "Kw"  PC

BO_ 2333601452 M2P_SUMDATA16__28: 8 MBMU
 SG_ M2P_PermitMaxVolt_B1_28 : 0|16@1+ (0.1,0) [0|6553.5] "V"  PC
 SG_ M2P_PermitMinVolt_B1_28 : 16|16@1+ (0.1,0) [0|6553.5] "V"  PC
 SG_ M2P_PermitMaxPow_Chg_B1_28 : 32|16@1+ (1,-20000) [-20000|45535] "Kw"  PC
 SG_ M2P_PermitMaxPow_DisChg_B1_28 : 48|16@1+ (1,-20000) [-20000|45535] "Kw"  PC

BO_ 2333601453 M2P_SUMDATA16__29: 8 MBMU
 SG_ M2P_PermitMaxVolt_B1_29 : 0|16@1+ (0.1,0) [0|6553.5] "V"  PC
 SG_ M2P_PermitMinVolt_B1_29 : 16|16@1+ (0.1,0) [0|6553.5] "V"  PC
 SG_ M2P_PermitMaxPow_Chg_B1_29 : 32|16@1+ (1,-20000) [-20000|45535] "Kw"  PC
 SG_ M2P_PermitMaxPow_DisChg_B1_29 : 48|16@1+ (1,-20000) [-20000|45535] "Kw"  PC

BO_ 2333601454 M2P_SUMDATA16__30: 8 MBMU
 SG_ M2P_PermitMaxVolt_B1_30 : 0|16@1+ (0.1,0) [0|6553.5] "V"  PC
 SG_ M2P_PermitMinVolt_B1_30 : 16|16@1+ (0.1,0) [0|6553.5] "V"  PC
 SG_ M2P_PermitMaxPow_Chg_B1_30 : 32|16@1+ (1,-20000) [-20000|45535] "Kw"  PC
 SG_ M2P_PermitMaxPow_DisChg_B1_30 : 48|16@1+ (1,-20000) [-20000|45535] "Kw"  PC

BO_ 2333601455 M2P_SUMDATA16__31: 8 MBMU
 SG_ M2P_PermitMaxVolt_B1_31 : 0|16@1+ (0.1,0) [0|6553.5] "V"  PC
 SG_ M2P_PermitMinVolt_B1_31 : 16|16@1+ (0.1,0) [0|6553.5] "V"  PC
 SG_ M2P_PermitMaxPow_Chg_B1_31 : 32|16@1+ (1,-20000) [-20000|45535] "Kw"  PC
 SG_ M2P_PermitMaxPow_DisChg_B1_31 : 48|16@1+ (1,-20000) [-20000|45535] "Kw"  PC

BO_ 2333666961 M2P_SUMDATA17__01: 8 MBMU
 SG_ M2P_Power_B1_01 : 0|16@1+ (1,-20000) [-20000|45535] "Kw"  PC
 SG_ M2P_SysremEngy_Chg_B1_01 : 16|16@1+ (1,0) [0|65535] "Kwh"  PC
 SG_ M2P_SysremEngy_DisChg_B1_01 : 32|16@1+ (1,0) [0|65535] "Kwh"  PC
 SG_ M2P_SysMaxVolt_B1_01 : 48|16@1+ (1,0) [0|65535] "mv"  PC

BO_ 2333666962 M2P_SUMDATA17__02: 8 MBMU
 SG_ M2P_Power_B1_02 : 0|16@1+ (1,-20000) [-20000|45535] "Kw"  PC
 SG_ M2P_SysremEngy_Chg_B1_02 : 16|16@1+ (1,0) [0|65535] "Kwh"  PC
 SG_ M2P_SysremEngy_DisChg_B1_02 : 32|16@1+ (1,0) [0|65535] "Kwh"  PC
 SG_ M2P_SysMaxVolt_B1_02 : 48|16@1+ (1,0) [0|65535] "mv"  PC

BO_ 2333666963 M2P_SUMDATA17__03: 8 MBMU
 SG_ M2P_Power_B1_03 : 0|16@1+ (1,-20000) [-20000|45535] "Kw"  PC
 SG_ M2P_SysremEngy_Chg_B1_03 : 16|16@1+ (1,0) [0|65535] "Kwh"  PC
 SG_ M2P_SysremEngy_DisChg_B1_03 : 32|16@1+ (1,0) [0|65535] "Kwh"  PC
 SG_ M2P_SysMaxVolt_B1_03 : 48|16@1+ (1,0) [0|65535] "mv"  PC

BO_ 2333666964 M2P_SUMDATA17__04: 8 MBMU
 SG_ M2P_Power_B1_04 : 0|16@1+ (1,-20000) [-20000|45535] "Kw"  PC
 SG_ M2P_SysremEngy_Chg_B1_04 : 16|16@1+ (1,0) [0|65535] "Kwh"  PC
 SG_ M2P_SysremEngy_DisChg_B1_04 : 32|16@1+ (1,0) [0|65535] "Kwh"  PC
 SG_ M2P_SysMaxVolt_B1_04 : 48|16@1+ (1,0) [0|65535] "mv"  PC

BO_ 2333666965 M2P_SUMDATA17__05: 8 MBMU
 SG_ M2P_Power_B1_05 : 0|16@1+ (1,-20000) [-20000|45535] "Kw"  PC
 SG_ M2P_SysremEngy_Chg_B1_05 : 16|16@1+ (1,0) [0|65535] "Kwh"  PC
 SG_ M2P_SysremEngy_DisChg_B1_05 : 32|16@1+ (1,0) [0|65535] "Kwh"  PC
 SG_ M2P_SysMaxVolt_B1_05 : 48|16@1+ (1,0) [0|65535] "mv"  PC

BO_ 2333666966 M2P_SUMDATA17__06: 8 MBMU
 SG_ M2P_Power_B1_06 : 0|16@1+ (1,-20000) [-20000|45535] "Kw"  PC
 SG_ M2P_SysremEngy_Chg_B1_06 : 16|16@1+ (1,0) [0|65535] "Kwh"  PC
 SG_ M2P_SysremEngy_DisChg_B1_06 : 32|16@1+ (1,0) [0|65535] "Kwh"  PC
 SG_ M2P_SysMaxVolt_B1_06 : 48|16@1+ (1,0) [0|65535] "mv"  PC

BO_ 2333666967 M2P_SUMDATA17__07: 8 MBMU
 SG_ M2P_Power_B1_07 : 0|16@1+ (1,-20000) [-20000|45535] "Kw"  PC
 SG_ M2P_SysremEngy_Chg_B1_07 : 16|16@1+ (1,0) [0|65535] "Kwh"  PC
 SG_ M2P_SysremEngy_DisChg_B1_07 : 32|16@1+ (1,0) [0|65535] "Kwh"  PC
 SG_ M2P_SysMaxVolt_B1_07 : 48|16@1+ (1,0) [0|65535] "mv"  PC

BO_ 2333666968 M2P_SUMDATA17__08: 8 MBMU
 SG_ M2P_Power_B1_08 : 0|16@1+ (1,-20000) [-20000|45535] "Kw"  PC
 SG_ M2P_SysremEngy_Chg_B1_08 : 16|16@1+ (1,0) [0|65535] "Kwh"  PC
 SG_ M2P_SysremEngy_DisChg_B1_08 : 32|16@1+ (1,0) [0|65535] "Kwh"  PC
 SG_ M2P_SysMaxVolt_B1_08 : 48|16@1+ (1,0) [0|65535] "mv"  PC

BO_ 2333666969 M2P_SUMDATA17__09: 8 MBMU
 SG_ M2P_Power_B1_09 : 0|16@1+ (1,-20000) [-20000|45535] "Kw"  PC
 SG_ M2P_SysremEngy_Chg_B1_09 : 16|16@1+ (1,0) [0|65535] "Kwh"  PC
 SG_ M2P_SysremEngy_DisChg_B1_09 : 32|16@1+ (1,0) [0|65535] "Kwh"  PC
 SG_ M2P_SysMaxVolt_B1_09 : 48|16@1+ (1,0) [0|65535] "mv"  PC

BO_ 2333666970 M2P_SUMDATA17__10: 8 MBMU
 SG_ M2P_Power_B1_10 : 0|16@1+ (1,-20000) [-20000|45535] "Kw"  PC
 SG_ M2P_SysremEngy_Chg_B1_10 : 16|16@1+ (1,0) [0|65535] "Kwh"  PC
 SG_ M2P_SysremEngy_DisChg_B1_10 : 32|16@1+ (1,0) [0|65535] "Kwh"  PC
 SG_ M2P_SysMaxVolt_B1_10 : 48|16@1+ (1,0) [0|65535] "mv"  PC

BO_ 2333666971 M2P_SUMDATA17__11: 8 MBMU
 SG_ M2P_Power_B1_11 : 0|16@1+ (1,-20000) [-20000|45535] "Kw"  PC
 SG_ M2P_SysremEngy_Chg_B1_11 : 16|16@1+ (1,0) [0|65535] "Kwh"  PC
 SG_ M2P_SysremEngy_DisChg_B1_11 : 32|16@1+ (1,0) [0|65535] "Kwh"  PC
 SG_ M2P_SysMaxVolt_B1_11 : 48|16@1+ (1,0) [0|65535] "mv"  PC

BO_ 2333666972 M2P_SUMDATA17__12: 8 MBMU
 SG_ M2P_Power_B1_12 : 0|16@1+ (1,-20000) [-20000|45535] "Kw"  PC
 SG_ M2P_SysremEngy_Chg_B1_12 : 16|16@1+ (1,0) [0|65535] "Kwh"  PC
 SG_ M2P_SysremEngy_DisChg_B1_12 : 32|16@1+ (1,0) [0|65535] "Kwh"  PC
 SG_ M2P_SysMaxVolt_B1_12 : 48|16@1+ (1,0) [0|65535] "mv"  PC

BO_ 2333666973 M2P_SUMDATA17__13: 8 MBMU
 SG_ M2P_Power_B1_13 : 0|16@1+ (1,-20000) [-20000|45535] "Kw"  PC
 SG_ M2P_SysremEngy_Chg_B1_13 : 16|16@1+ (1,0) [0|65535] "Kwh"  PC
 SG_ M2P_SysremEngy_DisChg_B1_13 : 32|16@1+ (1,0) [0|65535] "Kwh"  PC
 SG_ M2P_SysMaxVolt_B1_13 : 48|16@1+ (1,0) [0|65535] "mv"  PC

BO_ 2333666974 M2P_SUMDATA17__14: 8 MBMU
 SG_ M2P_Power_B1_14 : 0|16@1+ (1,-20000) [-20000|45535] "Kw"  PC
 SG_ M2P_SysremEngy_Chg_B1_14 : 16|16@1+ (1,0) [0|65535] "Kwh"  PC
 SG_ M2P_SysremEngy_DisChg_B1_14 : 32|16@1+ (1,0) [0|65535] "Kwh"  PC
 SG_ M2P_SysMaxVolt_B1_14 : 48|16@1+ (1,0) [0|65535] "mv"  PC

BO_ 2333666975 M2P_SUMDATA17__15: 8 MBMU
 SG_ M2P_Power_B1_15 : 0|16@1+ (1,-20000) [-20000|45535] "Kw"  PC
 SG_ M2P_SysremEngy_Chg_B1_15 : 16|16@1+ (1,0) [0|65535] "Kwh"  PC
 SG_ M2P_SysremEngy_DisChg_B1_15 : 32|16@1+ (1,0) [0|65535] "Kwh"  PC
 SG_ M2P_SysMaxVolt_B1_15 : 48|16@1+ (1,0) [0|65535] "mv"  PC

BO_ 2333666976 M2P_SUMDATA17__16: 8 MBMU
 SG_ M2P_Power_B1_16 : 0|16@1+ (1,-20000) [-20000|45535] "Kw"  PC
 SG_ M2P_SysremEngy_Chg_B1_16 : 16|16@1+ (1,0) [0|65535] "Kwh"  PC
 SG_ M2P_SysremEngy_DisChg_B1_16 : 32|16@1+ (1,0) [0|65535] "Kwh"  PC
 SG_ M2P_SysMaxVolt_B1_16 : 48|16@1+ (1,0) [0|65535] "mv"  PC

BO_ 2333666977 M2P_SUMDATA17__17: 8 MBMU
 SG_ M2P_Power_B1_17 : 0|16@1+ (1,-20000) [-20000|45535] "Kw"  PC
 SG_ M2P_SysremEngy_Chg_B1_17 : 16|16@1+ (1,0) [0|65535] "Kwh"  PC
 SG_ M2P_SysremEngy_DisChg_B1_17 : 32|16@1+ (1,0) [0|65535] "Kwh"  PC
 SG_ M2P_SysMaxVolt_B1_17 : 48|16@1+ (1,0) [0|65535] "mv"  PC

BO_ 2333666978 M2P_SUMDATA17__18: 8 MBMU
 SG_ M2P_Power_B1_18 : 0|16@1+ (1,-20000) [-20000|45535] "Kw"  PC
 SG_ M2P_SysremEngy_Chg_B1_18 : 16|16@1+ (1,0) [0|65535] "Kwh"  PC
 SG_ M2P_SysremEngy_DisChg_B1_18 : 32|16@1+ (1,0) [0|65535] "Kwh"  PC
 SG_ M2P_SysMaxVolt_B1_18 : 48|16@1+ (1,0) [0|65535] "mv"  PC

BO_ 2333666979 M2P_SUMDATA17__19: 8 MBMU
 SG_ M2P_Power_B1_19 : 0|16@1+ (1,-20000) [-20000|45535] "Kw"  PC
 SG_ M2P_SysremEngy_Chg_B1_19 : 16|16@1+ (1,0) [0|65535] "Kwh"  PC
 SG_ M2P_SysremEngy_DisChg_B1_19 : 32|16@1+ (1,0) [0|65535] "Kwh"  PC
 SG_ M2P_SysMaxVolt_B1_19 : 48|16@1+ (1,0) [0|65535] "mv"  PC

BO_ 2333666980 M2P_SUMDATA17__20: 8 MBMU
 SG_ M2P_Power_B1_20 : 0|16@1+ (1,-20000) [-20000|45535] "Kw"  PC
 SG_ M2P_SysremEngy_Chg_B1_20 : 16|16@1+ (1,0) [0|65535] "Kwh"  PC
 SG_ M2P_SysremEngy_DisChg_B1_20 : 32|16@1+ (1,0) [0|65535] "Kwh"  PC
 SG_ M2P_SysMaxVolt_B1_20 : 48|16@1+ (1,0) [0|65535] "mv"  PC

BO_ 2333666981 M2P_SUMDATA17__21: 8 MBMU
 SG_ M2P_Power_B1_21 : 0|16@1+ (1,-20000) [-20000|45535] "Kw"  PC
 SG_ M2P_SysremEngy_Chg_B1_21 : 16|16@1+ (1,0) [0|65535] "Kwh"  PC
 SG_ M2P_SysremEngy_DisChg_B1_21 : 32|16@1+ (1,0) [0|65535] "Kwh"  PC
 SG_ M2P_SysMaxVolt_B1_21 : 48|16@1+ (1,0) [0|65535] "mv"  PC

BO_ 2333666982 M2P_SUMDATA17__22: 8 MBMU
 SG_ M2P_Power_B1_22 : 0|16@1+ (1,-20000) [-20000|45535] "Kw"  PC
 SG_ M2P_SysremEngy_Chg_B1_22 : 16|16@1+ (1,0) [0|65535] "Kwh"  PC
 SG_ M2P_SysremEngy_DisChg_B1_22 : 32|16@1+ (1,0) [0|65535] "Kwh"  PC
 SG_ M2P_SysMaxVolt_B1_22 : 48|16@1+ (1,0) [0|65535] "mv"  PC

BO_ 2333666983 M2P_SUMDATA17__23: 8 MBMU
 SG_ M2P_Power_B1_23 : 0|16@1+ (1,-20000) [-20000|45535] "Kw"  PC
 SG_ M2P_SysremEngy_Chg_B1_23 : 16|16@1+ (1,0) [0|65535] "Kwh"  PC
 SG_ M2P_SysremEngy_DisChg_B1_23 : 32|16@1+ (1,0) [0|65535] "Kwh"  PC
 SG_ M2P_SysMaxVolt_B1_23 : 48|16@1+ (1,0) [0|65535] "mv"  PC

BO_ 2333666984 M2P_SUMDATA17__24: 8 MBMU
 SG_ M2P_Power_B1_24 : 0|16@1+ (1,-20000) [-20000|45535] "Kw"  PC
 SG_ M2P_SysremEngy_Chg_B1_24 : 16|16@1+ (1,0) [0|65535] "Kwh"  PC
 SG_ M2P_SysremEngy_DisChg_B1_24 : 32|16@1+ (1,0) [0|65535] "Kwh"  PC
 SG_ M2P_SysMaxVolt_B1_24 : 48|16@1+ (1,0) [0|65535] "mv"  PC

BO_ 2333666985 M2P_SUMDATA17__25: 8 MBMU
 SG_ M2P_Power_B1_25 : 0|16@1+ (1,-20000) [-20000|45535] "Kw"  PC
 SG_ M2P_SysremEngy_Chg_B1_25 : 16|16@1+ (1,0) [0|65535] "Kwh"  PC
 SG_ M2P_SysremEngy_DisChg_B1_25 : 32|16@1+ (1,0) [0|65535] "Kwh"  PC
 SG_ M2P_SysMaxVolt_B1_25 : 48|16@1+ (1,0) [0|65535] "mv"  PC

BO_ 2333666986 M2P_SUMDATA17__26: 8 MBMU
 SG_ M2P_Power_B1_26 : 0|16@1+ (1,-20000) [-20000|45535] "Kw"  PC
 SG_ M2P_SysremEngy_Chg_B1_26 : 16|16@1+ (1,0) [0|65535] "Kwh"  PC
 SG_ M2P_SysremEngy_DisChg_B1_26 : 32|16@1+ (1,0) [0|65535] "Kwh"  PC
 SG_ M2P_SysMaxVolt_B1_26 : 48|16@1+ (1,0) [0|65535] "mv"  PC

BO_ 2333666987 M2P_SUMDATA17__27: 8 MBMU
 SG_ M2P_Power_B1_27 : 0|16@1+ (1,-20000) [-20000|45535] "Kw"  PC
 SG_ M2P_SysremEngy_Chg_B1_27 : 16|16@1+ (1,0) [0|65535] "Kwh"  PC
 SG_ M2P_SysremEngy_DisChg_B1_27 : 32|16@1+ (1,0) [0|65535] "Kwh"  PC
 SG_ M2P_SysMaxVolt_B1_27 : 48|16@1+ (1,0) [0|65535] "mv"  PC

BO_ 2333666988 M2P_SUMDATA17__28: 8 MBMU
 SG_ M2P_Power_B1_28 : 0|16@1+ (1,-20000) [-20000|45535] "Kw"  PC
 SG_ M2P_SysremEngy_Chg_B1_28 : 16|16@1+ (1,0) [0|65535] "Kwh"  PC
 SG_ M2P_SysremEngy_DisChg_B1_28 : 32|16@1+ (1,0) [0|65535] "Kwh"  PC
 SG_ M2P_SysMaxVolt_B1_28 : 48|16@1+ (1,0) [0|65535] "mv"  PC

BO_ 2333666989 M2P_SUMDATA17__29: 8 MBMU
 SG_ M2P_Power_B1_29 : 0|16@1+ (1,-20000) [-20000|45535] "Kw"  PC
 SG_ M2P_SysremEngy_Chg_B1_29 : 16|16@1+ (1,0) [0|65535] "Kwh"  PC
 SG_ M2P_SysremEngy_DisChg_B1_29 : 32|16@1+ (1,0) [0|65535] "Kwh"  PC
 SG_ M2P_SysMaxVolt_B1_29 : 48|16@1+ (1,0) [0|65535] "mv"  PC

BO_ 2333666990 M2P_SUMDATA17__30: 8 MBMU
 SG_ M2P_Power_B1_30 : 0|16@1+ (1,-20000) [-20000|45535] "Kw"  PC
 SG_ M2P_SysremEngy_Chg_B1_30 : 16|16@1+ (1,0) [0|65535] "Kwh"  PC
 SG_ M2P_SysremEngy_DisChg_B1_30 : 32|16@1+ (1,0) [0|65535] "Kwh"  PC
 SG_ M2P_SysMaxVolt_B1_30 : 48|16@1+ (1,0) [0|65535] "mv"  PC

BO_ 2333666991 M2P_SUMDATA17__31: 8 MBMU
 SG_ M2P_Power_B1_31 : 0|16@1+ (1,-20000) [-20000|45535] "Kw"  PC
 SG_ M2P_SysremEngy_Chg_B1_31 : 16|16@1+ (1,0) [0|65535] "Kwh"  PC
 SG_ M2P_SysremEngy_DisChg_B1_31 : 32|16@1+ (1,0) [0|65535] "Kwh"  PC
 SG_ M2P_SysMaxVolt_B1_31 : 48|16@1+ (1,0) [0|65535] "mv"  PC

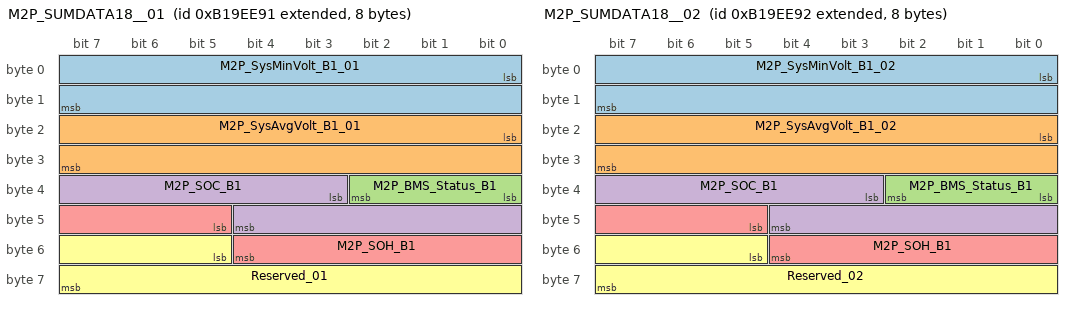
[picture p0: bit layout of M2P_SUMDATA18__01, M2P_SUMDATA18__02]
BO_ 2333732497 M2P_SUMDATA18__01: 8 MBMU
 SG_ M2P_SysMinVolt_B1_01 : 0|16@1+ (1,0) [0|65535] "mv"  PC
 SG_ M2P_SysAvgVolt_B1_01 : 16|16@1+ (1,0) [0|65535] "mv"  PC
 SG_ M2P_BMS_Status_B1 : 32|3@1+ (1,0) [0|7] ""  PC
 SG_ M2P_SOC_B1 : 35|10@1+ (0.1,0) [0|102.3] "%"  PC
 SG_ M2P_SOH_B1 : 45|8@1+ (1,0) [0|255] "%"  PC
 SG_ Reserved_01 : 53|11@1+ (1,0) [0|2047] ""  PC

BO_ 2333732498 M2P_SUMDATA18__02: 8 MBMU
 SG_ M2P_SysMinVolt_B1_02 : 0|16@1+ (1,0) [0|65535] "mv"  PC
 SG_ M2P_SysAvgVolt_B1_02 : 16|16@1+ (1,0) [0|65535] "mv"  PC
 SG_ M2P_BMS_Status_B1 : 32|3@1+ (1,0) [0|7] ""  PC
 SG_ M2P_SOC_B1 : 35|10@1+ (0.1,0) [0|102.3] "%"  PC
 SG_ M2P_SOH_B1 : 45|8@1+ (1,0) [0|255] "%"  PC
 SG_ Reserved_02 : 53|11@1+ (1,0) [0|2047] ""  PC

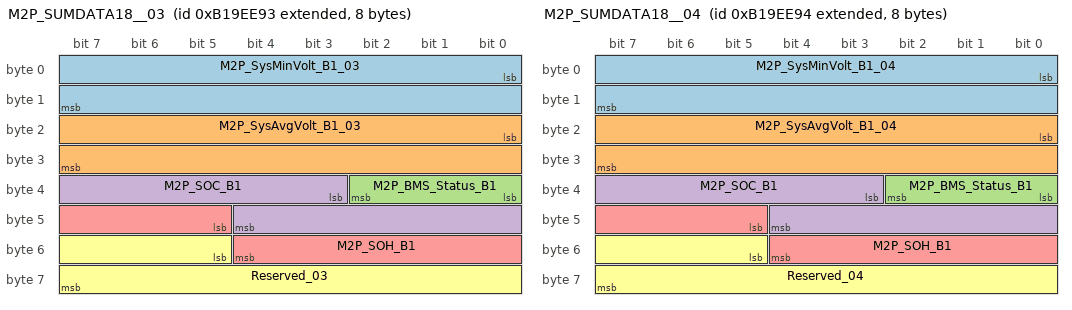
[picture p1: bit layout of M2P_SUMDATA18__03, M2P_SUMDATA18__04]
BO_ 2333732499 M2P_SUMDATA18__03: 8 MBMU
 SG_ M2P_SysMinVolt_B1_03 : 0|16@1+ (1,0) [0|65535] "mv"  PC
 SG_ M2P_SysAvgVolt_B1_03 : 16|16@1+ (1,0) [0|65535] "mv"  PC
 SG_ M2P_BMS_Status_B1 : 32|3@1+ (1,0) [0|7] ""  PC
 SG_ M2P_SOC_B1 : 35|10@1+ (0.1,0) [0|102.3] "%"  PC
 SG_ M2P_SOH_B1 : 45|8@1+ (1,0) [0|255] "%"  PC
 SG_ Reserved_03 : 53|11@1+ (1,0) [0|2047] ""  PC

BO_ 2333732500 M2P_SUMDATA18__04: 8 MBMU
 SG_ M2P_SysMinVolt_B1_04 : 0|16@1+ (1,0) [0|65535] "mv"  PC
 SG_ M2P_SysAvgVolt_B1_04 : 16|16@1+ (1,0) [0|65535] "mv"  PC
 SG_ M2P_BMS_Status_B1 : 32|3@1+ (1,0) [0|7] ""  PC
 SG_ M2P_SOC_B1 : 35|10@1+ (0.1,0) [0|102.3] "%"  PC
 SG_ M2P_SOH_B1 : 45|8@1+ (1,0) [0|255] "%"  PC
 SG_ Reserved_04 : 53|11@1+ (1,0) [0|2047] ""  PC

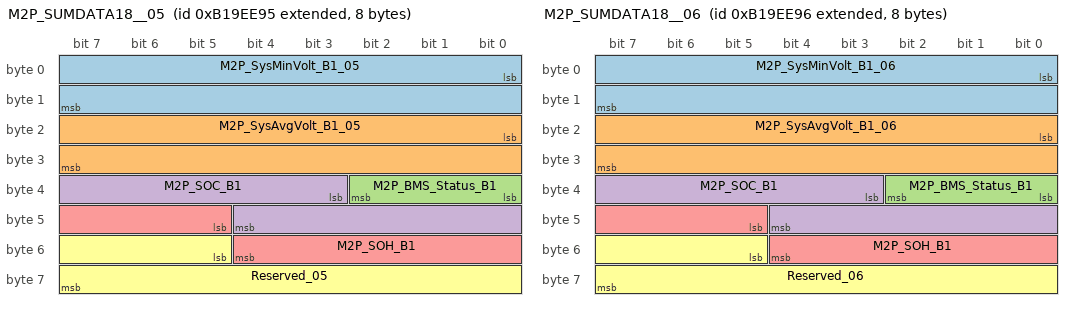
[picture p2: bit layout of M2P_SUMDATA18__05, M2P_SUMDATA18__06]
BO_ 2333732501 M2P_SUMDATA18__05: 8 MBMU
 SG_ M2P_SysMinVolt_B1_05 : 0|16@1+ (1,0) [0|65535] "mv"  PC
 SG_ M2P_SysAvgVolt_B1_05 : 16|16@1+ (1,0) [0|65535] "mv"  PC
 SG_ M2P_BMS_Status_B1 : 32|3@1+ (1,0) [0|7] ""  PC
 SG_ M2P_SOC_B1 : 35|10@1+ (0.1,0) [0|102.3] "%"  PC
 SG_ M2P_SOH_B1 : 45|8@1+ (1,0) [0|255] "%"  PC
 SG_ Reserved_05 : 53|11@1+ (1,0) [0|2047] ""  PC

BO_ 2333732502 M2P_SUMDATA18__06: 8 MBMU
 SG_ M2P_SysMinVolt_B1_06 : 0|16@1+ (1,0) [0|65535] "mv"  PC
 SG_ M2P_SysAvgVolt_B1_06 : 16|16@1+ (1,0) [0|65535] "mv"  PC
 SG_ M2P_BMS_Status_B1 : 32|3@1+ (1,0) [0|7] ""  PC
 SG_ M2P_SOC_B1 : 35|10@1+ (0.1,0) [0|102.3] "%"  PC
 SG_ M2P_SOH_B1 : 45|8@1+ (1,0) [0|255] "%"  PC
 SG_ Reserved_06 : 53|11@1+ (1,0) [0|2047] ""  PC

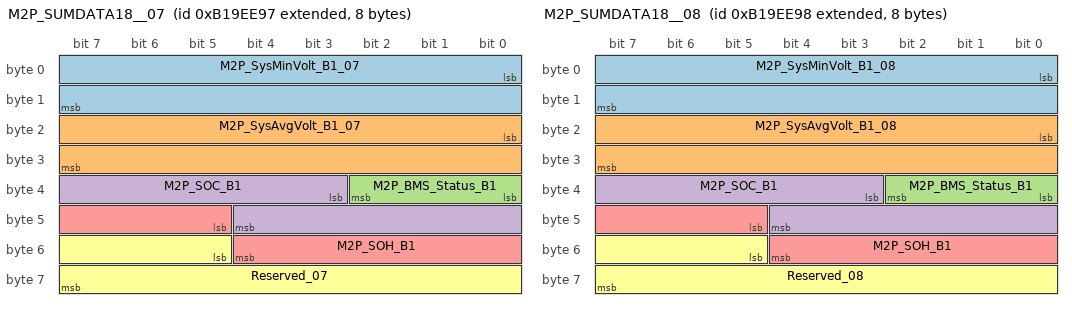
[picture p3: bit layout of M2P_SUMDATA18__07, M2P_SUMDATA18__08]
BO_ 2333732503 M2P_SUMDATA18__07: 8 MBMU
 SG_ M2P_SysMinVolt_B1_07 : 0|16@1+ (1,0) [0|65535] "mv"  PC
 SG_ M2P_SysAvgVolt_B1_07 : 16|16@1+ (1,0) [0|65535] "mv"  PC
 SG_ M2P_BMS_Status_B1 : 32|3@1+ (1,0) [0|7] ""  PC
 SG_ M2P_SOC_B1 : 35|10@1+ (0.1,0) [0|102.3] "%"  PC
 SG_ M2P_SOH_B1 : 45|8@1+ (1,0) [0|255] "%"  PC
 SG_ Reserved_07 : 53|11@1+ (1,0) [0|2047] ""  PC

BO_ 2333732504 M2P_SUMDATA18__08: 8 MBMU
 SG_ M2P_SysMinVolt_B1_08 : 0|16@1+ (1,0) [0|65535] "mv"  PC
 SG_ M2P_SysAvgVolt_B1_08 : 16|16@1+ (1,0) [0|65535] "mv"  PC
 SG_ M2P_BMS_Status_B1 : 32|3@1+ (1,0) [0|7] ""  PC
 SG_ M2P_SOC_B1 : 35|10@1+ (0.1,0) [0|102.3] "%"  PC
 SG_ M2P_SOH_B1 : 45|8@1+ (1,0) [0|255] "%"  PC
 SG_ Reserved_08 : 53|11@1+ (1,0) [0|2047] ""  PC

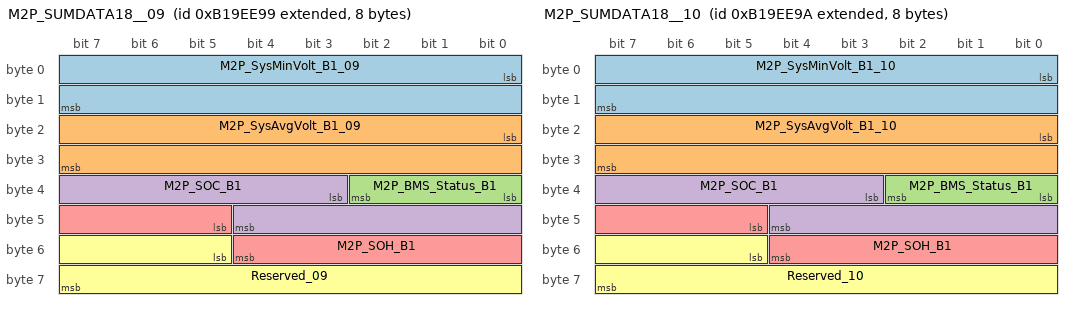
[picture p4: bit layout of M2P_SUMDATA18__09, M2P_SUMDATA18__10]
BO_ 2333732505 M2P_SUMDATA18__09: 8 MBMU
 SG_ M2P_SysMinVolt_B1_09 : 0|16@1+ (1,0) [0|65535] "mv"  PC
 SG_ M2P_SysAvgVolt_B1_09 : 16|16@1+ (1,0) [0|65535] "mv"  PC
 SG_ M2P_BMS_Status_B1 : 32|3@1+ (1,0) [0|7] ""  PC
 SG_ M2P_SOC_B1 : 35|10@1+ (0.1,0) [0|102.3] "%"  PC
 SG_ M2P_SOH_B1 : 45|8@1+ (1,0) [0|255] "%"  PC
 SG_ Reserved_09 : 53|11@1+ (1,0) [0|2047] ""  PC

BO_ 2333732506 M2P_SUMDATA18__10: 8 MBMU
 SG_ M2P_SysMinVolt_B1_10 : 0|16@1+ (1,0) [0|65535] "mv"  PC
 SG_ M2P_SysAvgVolt_B1_10 : 16|16@1+ (1,0) [0|65535] "mv"  PC
 SG_ M2P_BMS_Status_B1 : 32|3@1+ (1,0) [0|7] ""  PC
 SG_ M2P_SOC_B1 : 35|10@1+ (0.1,0) [0|102.3] "%"  PC
 SG_ M2P_SOH_B1 : 45|8@1+ (1,0) [0|255] "%"  PC
 SG_ Reserved_10 : 53|11@1+ (1,0) [0|2047] ""  PC

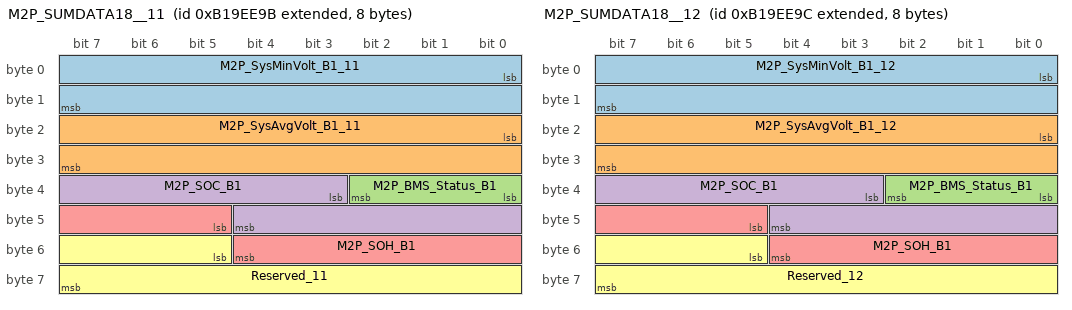
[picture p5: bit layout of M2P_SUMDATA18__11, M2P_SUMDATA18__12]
BO_ 2333732507 M2P_SUMDATA18__11: 8 MBMU
 SG_ M2P_SysMinVolt_B1_11 : 0|16@1+ (1,0) [0|65535] "mv"  PC
 SG_ M2P_SysAvgVolt_B1_11 : 16|16@1+ (1,0) [0|65535] "mv"  PC
 SG_ M2P_BMS_Status_B1 : 32|3@1+ (1,0) [0|7] ""  PC
 SG_ M2P_SOC_B1 : 35|10@1+ (0.1,0) [0|102.3] "%"  PC
 SG_ M2P_SOH_B1 : 45|8@1+ (1,0) [0|255] "%"  PC
 SG_ Reserved_11 : 53|11@1+ (1,0) [0|2047] ""  PC

BO_ 2333732508 M2P_SUMDATA18__12: 8 MBMU
 SG_ M2P_SysMinVolt_B1_12 : 0|16@1+ (1,0) [0|65535] "mv"  PC
 SG_ M2P_SysAvgVolt_B1_12 : 16|16@1+ (1,0) [0|65535] "mv"  PC
 SG_ M2P_BMS_Status_B1 : 32|3@1+ (1,0) [0|7] ""  PC
 SG_ M2P_SOC_B1 : 35|10@1+ (0.1,0) [0|102.3] "%"  PC
 SG_ M2P_SOH_B1 : 45|8@1+ (1,0) [0|255] "%"  PC
 SG_ Reserved_12 : 53|11@1+ (1,0) [0|2047] ""  PC

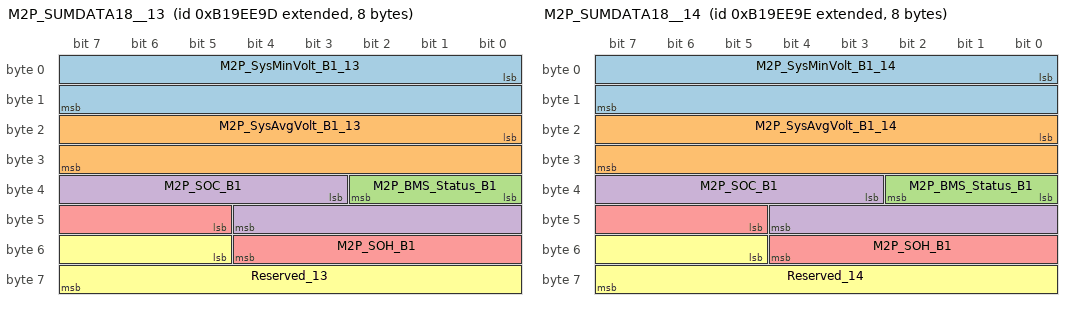
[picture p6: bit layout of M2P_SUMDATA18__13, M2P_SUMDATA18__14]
BO_ 2333732509 M2P_SUMDATA18__13: 8 MBMU
 SG_ M2P_SysMinVolt_B1_13 : 0|16@1+ (1,0) [0|65535] "mv"  PC
 SG_ M2P_SysAvgVolt_B1_13 : 16|16@1+ (1,0) [0|65535] "mv"  PC
 SG_ M2P_BMS_Status_B1 : 32|3@1+ (1,0) [0|7] ""  PC
 SG_ M2P_SOC_B1 : 35|10@1+ (0.1,0) [0|102.3] "%"  PC
 SG_ M2P_SOH_B1 : 45|8@1+ (1,0) [0|255] "%"  PC
 SG_ Reserved_13 : 53|11@1+ (1,0) [0|2047] ""  PC

BO_ 2333732510 M2P_SUMDATA18__14: 8 MBMU
 SG_ M2P_SysMinVolt_B1_14 : 0|16@1+ (1,0) [0|65535] "mv"  PC
 SG_ M2P_SysAvgVolt_B1_14 : 16|16@1+ (1,0) [0|65535] "mv"  PC
 SG_ M2P_BMS_Status_B1 : 32|3@1+ (1,0) [0|7] ""  PC
 SG_ M2P_SOC_B1 : 35|10@1+ (0.1,0) [0|102.3] "%"  PC
 SG_ M2P_SOH_B1 : 45|8@1+ (1,0) [0|255] "%"  PC
 SG_ Reserved_14 : 53|11@1+ (1,0) [0|2047] ""  PC

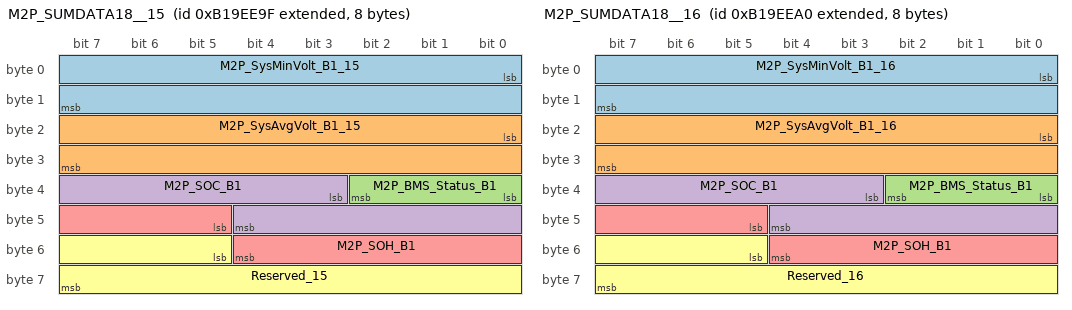
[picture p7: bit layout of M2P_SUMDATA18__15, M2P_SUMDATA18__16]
BO_ 2333732511 M2P_SUMDATA18__15: 8 MBMU
 SG_ M2P_SysMinVolt_B1_15 : 0|16@1+ (1,0) [0|65535] "mv"  PC
 SG_ M2P_SysAvgVolt_B1_15 : 16|16@1+ (1,0) [0|65535] "mv"  PC
 SG_ M2P_BMS_Status_B1 : 32|3@1+ (1,0) [0|7] ""  PC
 SG_ M2P_SOC_B1 : 35|10@1+ (0.1,0) [0|102.3] "%"  PC
 SG_ M2P_SOH_B1 : 45|8@1+ (1,0) [0|255] "%"  PC
 SG_ Reserved_15 : 53|11@1+ (1,0) [0|2047] ""  PC

BO_ 2333732512 M2P_SUMDATA18__16: 8 MBMU
 SG_ M2P_SysMinVolt_B1_16 : 0|16@1+ (1,0) [0|65535] "mv"  PC
 SG_ M2P_SysAvgVolt_B1_16 : 16|16@1+ (1,0) [0|65535] "mv"  PC
 SG_ M2P_BMS_Status_B1 : 32|3@1+ (1,0) [0|7] ""  PC
 SG_ M2P_SOC_B1 : 35|10@1+ (0.1,0) [0|102.3] "%"  PC
 SG_ M2P_SOH_B1 : 45|8@1+ (1,0) [0|255] "%"  PC
 SG_ Reserved_16 : 53|11@1+ (1,0) [0|2047] ""  PC

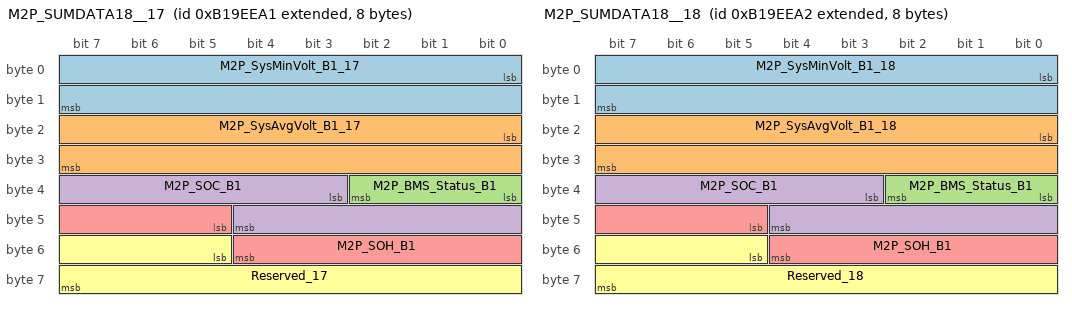
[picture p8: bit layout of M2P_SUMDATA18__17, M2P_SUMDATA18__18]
BO_ 2333732513 M2P_SUMDATA18__17: 8 MBMU
 SG_ M2P_SysMinVolt_B1_17 : 0|16@1+ (1,0) [0|65535] "mv"  PC
 SG_ M2P_SysAvgVolt_B1_17 : 16|16@1+ (1,0) [0|65535] "mv"  PC
 SG_ M2P_BMS_Status_B1 : 32|3@1+ (1,0) [0|7] ""  PC
 SG_ M2P_SOC_B1 : 35|10@1+ (0.1,0) [0|102.3] "%"  PC
 SG_ M2P_SOH_B1 : 45|8@1+ (1,0) [0|255] "%"  PC
 SG_ Reserved_17 : 53|11@1+ (1,0) [0|2047] ""  PC

BO_ 2333732514 M2P_SUMDATA18__18: 8 MBMU
 SG_ M2P_SysMinVolt_B1_18 : 0|16@1+ (1,0) [0|65535] "mv"  PC
 SG_ M2P_SysAvgVolt_B1_18 : 16|16@1+ (1,0) [0|65535] "mv"  PC
 SG_ M2P_BMS_Status_B1 : 32|3@1+ (1,0) [0|7] ""  PC
 SG_ M2P_SOC_B1 : 35|10@1+ (0.1,0) [0|102.3] "%"  PC
 SG_ M2P_SOH_B1 : 45|8@1+ (1,0) [0|255] "%"  PC
 SG_ Reserved_18 : 53|11@1+ (1,0) [0|2047] ""  PC

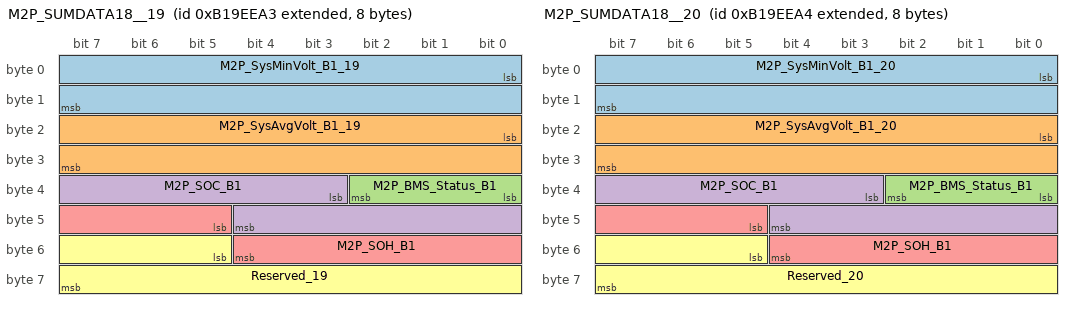
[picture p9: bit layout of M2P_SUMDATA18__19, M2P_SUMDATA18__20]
BO_ 2333732515 M2P_SUMDATA18__19: 8 MBMU
 SG_ M2P_SysMinVolt_B1_19 : 0|16@1+ (1,0) [0|65535] "mv"  PC
 SG_ M2P_SysAvgVolt_B1_19 : 16|16@1+ (1,0) [0|65535] "mv"  PC
 SG_ M2P_BMS_Status_B1 : 32|3@1+ (1,0) [0|7] ""  PC
 SG_ M2P_SOC_B1 : 35|10@1+ (0.1,0) [0|102.3] "%"  PC
 SG_ M2P_SOH_B1 : 45|8@1+ (1,0) [0|255] "%"  PC
 SG_ Reserved_19 : 53|11@1+ (1,0) [0|2047] ""  PC

BO_ 2333732516 M2P_SUMDATA18__20: 8 MBMU
 SG_ M2P_SysMinVolt_B1_20 : 0|16@1+ (1,0) [0|65535] "mv"  PC
 SG_ M2P_SysAvgVolt_B1_20 : 16|16@1+ (1,0) [0|65535] "mv"  PC
 SG_ M2P_BMS_Status_B1 : 32|3@1+ (1,0) [0|7] ""  PC
 SG_ M2P_SOC_B1 : 35|10@1+ (0.1,0) [0|102.3] "%"  PC
 SG_ M2P_SOH_B1 : 45|8@1+ (1,0) [0|255] "%"  PC
 SG_ Reserved_20 : 53|11@1+ (1,0) [0|2047] ""  PC

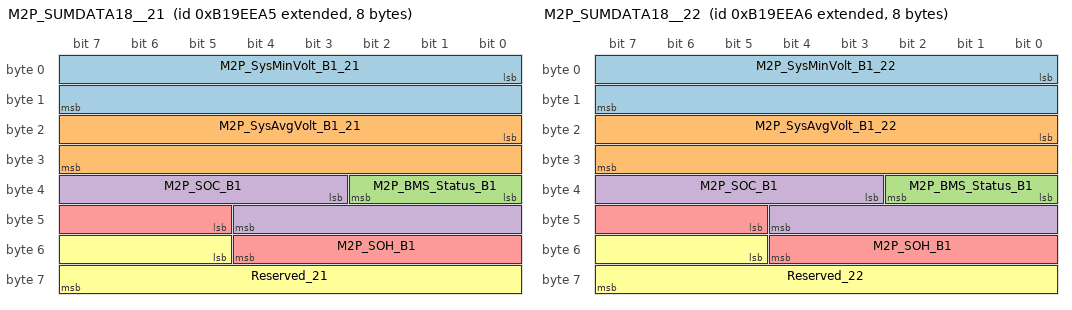
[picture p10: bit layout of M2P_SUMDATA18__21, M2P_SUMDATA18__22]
BO_ 2333732517 M2P_SUMDATA18__21: 8 MBMU
 SG_ M2P_SysMinVolt_B1_21 : 0|16@1+ (1,0) [0|65535] "mv"  PC
 SG_ M2P_SysAvgVolt_B1_21 : 16|16@1+ (1,0) [0|65535] "mv"  PC
 SG_ M2P_BMS_Status_B1 : 32|3@1+ (1,0) [0|7] ""  PC
 SG_ M2P_SOC_B1 : 35|10@1+ (0.1,0) [0|102.3] "%"  PC
 SG_ M2P_SOH_B1 : 45|8@1+ (1,0) [0|255] "%"  PC
 SG_ Reserved_21 : 53|11@1+ (1,0) [0|2047] ""  PC

BO_ 2333732518 M2P_SUMDATA18__22: 8 MBMU
 SG_ M2P_SysMinVolt_B1_22 : 0|16@1+ (1,0) [0|65535] "mv"  PC
 SG_ M2P_SysAvgVolt_B1_22 : 16|16@1+ (1,0) [0|65535] "mv"  PC
 SG_ M2P_BMS_Status_B1 : 32|3@1+ (1,0) [0|7] ""  PC
 SG_ M2P_SOC_B1 : 35|10@1+ (0.1,0) [0|102.3] "%"  PC
 SG_ M2P_SOH_B1 : 45|8@1+ (1,0) [0|255] "%"  PC
 SG_ Reserved_22 : 53|11@1+ (1,0) [0|2047] ""  PC

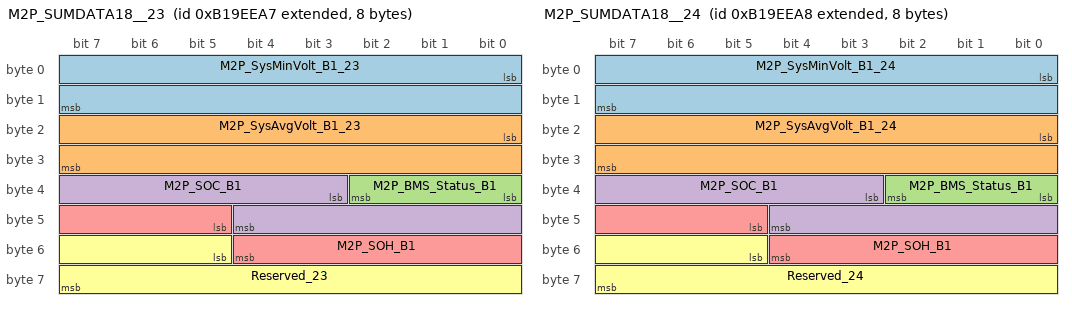
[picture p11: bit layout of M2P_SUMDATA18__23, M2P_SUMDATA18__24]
BO_ 2333732519 M2P_SUMDATA18__23: 8 MBMU
 SG_ M2P_SysMinVolt_B1_23 : 0|16@1+ (1,0) [0|65535] "mv"  PC
 SG_ M2P_SysAvgVolt_B1_23 : 16|16@1+ (1,0) [0|65535] "mv"  PC
 SG_ M2P_BMS_Status_B1 : 32|3@1+ (1,0) [0|7] ""  PC
 SG_ M2P_SOC_B1 : 35|10@1+ (0.1,0) [0|102.3] "%"  PC
 SG_ M2P_SOH_B1 : 45|8@1+ (1,0) [0|255] "%"  PC
 SG_ Reserved_23 : 53|11@1+ (1,0) [0|2047] ""  PC

BO_ 2333732520 M2P_SUMDATA18__24: 8 MBMU
 SG_ M2P_SysMinVolt_B1_24 : 0|16@1+ (1,0) [0|65535] "mv"  PC
 SG_ M2P_SysAvgVolt_B1_24 : 16|16@1+ (1,0) [0|65535] "mv"  PC
 SG_ M2P_BMS_Status_B1 : 32|3@1+ (1,0) [0|7] ""  PC
 SG_ M2P_SOC_B1 : 35|10@1+ (0.1,0) [0|102.3] "%"  PC
 SG_ M2P_SOH_B1 : 45|8@1+ (1,0) [0|255] "%"  PC
 SG_ Reserved_24 : 53|11@1+ (1,0) [0|2047] ""  PC

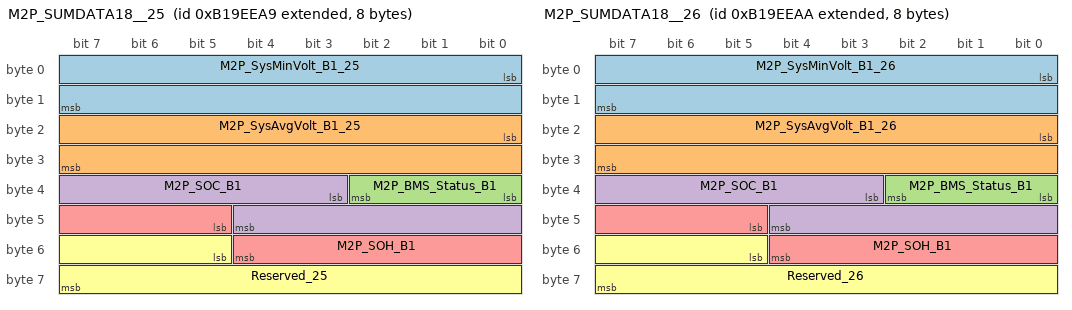
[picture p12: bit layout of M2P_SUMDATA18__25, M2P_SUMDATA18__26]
BO_ 2333732521 M2P_SUMDATA18__25: 8 MBMU
 SG_ M2P_SysMinVolt_B1_25 : 0|16@1+ (1,0) [0|65535] "mv"  PC
 SG_ M2P_SysAvgVolt_B1_25 : 16|16@1+ (1,0) [0|65535] "mv"  PC
 SG_ M2P_BMS_Status_B1 : 32|3@1+ (1,0) [0|7] ""  PC
 SG_ M2P_SOC_B1 : 35|10@1+ (0.1,0) [0|102.3] "%"  PC
 SG_ M2P_SOH_B1 : 45|8@1+ (1,0) [0|255] "%"  PC
 SG_ Reserved_25 : 53|11@1+ (1,0) [0|2047] ""  PC

BO_ 2333732522 M2P_SUMDATA18__26: 8 MBMU
 SG_ M2P_SysMinVolt_B1_26 : 0|16@1+ (1,0) [0|65535] "mv"  PC
 SG_ M2P_SysAvgVolt_B1_26 : 16|16@1+ (1,0) [0|65535] "mv"  PC
 SG_ M2P_BMS_Status_B1 : 32|3@1+ (1,0) [0|7] ""  PC
 SG_ M2P_SOC_B1 : 35|10@1+ (0.1,0) [0|102.3] "%"  PC
 SG_ M2P_SOH_B1 : 45|8@1+ (1,0) [0|255] "%"  PC
 SG_ Reserved_26 : 53|11@1+ (1,0) [0|2047] ""  PC

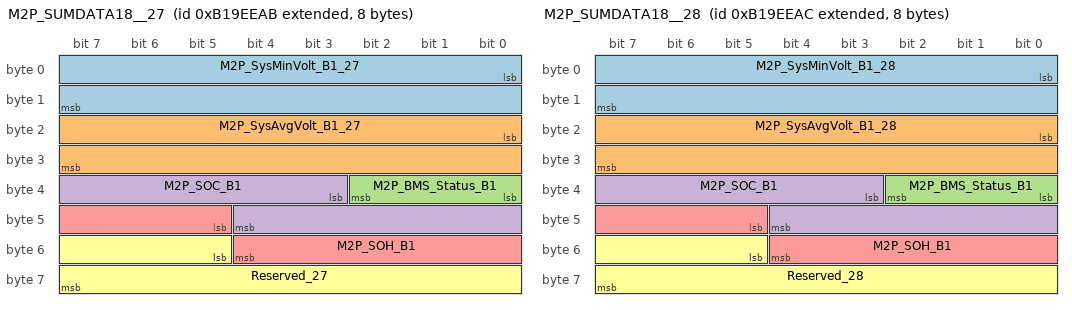
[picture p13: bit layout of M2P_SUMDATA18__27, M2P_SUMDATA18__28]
BO_ 2333732523 M2P_SUMDATA18__27: 8 MBMU
 SG_ M2P_SysMinVolt_B1_27 : 0|16@1+ (1,0) [0|65535] "mv"  PC
 SG_ M2P_SysAvgVolt_B1_27 : 16|16@1+ (1,0) [0|65535] "mv"  PC
 SG_ M2P_BMS_Status_B1 : 32|3@1+ (1,0) [0|7] ""  PC
 SG_ M2P_SOC_B1 : 35|10@1+ (0.1,0) [0|102.3] "%"  PC
 SG_ M2P_SOH_B1 : 45|8@1+ (1,0) [0|255] "%"  PC
 SG_ Reserved_27 : 53|11@1+ (1,0) [0|2047] ""  PC

BO_ 2333732524 M2P_SUMDATA18__28: 8 MBMU
 SG_ M2P_SysMinVolt_B1_28 : 0|16@1+ (1,0) [0|65535] "mv"  PC
 SG_ M2P_SysAvgVolt_B1_28 : 16|16@1+ (1,0) [0|65535] "mv"  PC
 SG_ M2P_BMS_Status_B1 : 32|3@1+ (1,0) [0|7] ""  PC
 SG_ M2P_SOC_B1 : 35|10@1+ (0.1,0) [0|102.3] "%"  PC
 SG_ M2P_SOH_B1 : 45|8@1+ (1,0) [0|255] "%"  PC
 SG_ Reserved_28 : 53|11@1+ (1,0) [0|2047] ""  PC

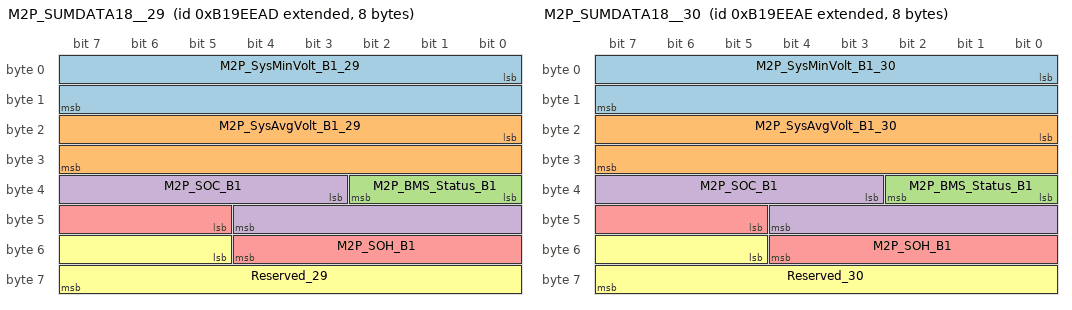
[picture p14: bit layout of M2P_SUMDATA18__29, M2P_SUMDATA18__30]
BO_ 2333732525 M2P_SUMDATA18__29: 8 MBMU
 SG_ M2P_SysMinVolt_B1_29 : 0|16@1+ (1,0) [0|65535] "mv"  PC
 SG_ M2P_SysAvgVolt_B1_29 : 16|16@1+ (1,0) [0|65535] "mv"  PC
 SG_ M2P_BMS_Status_B1 : 32|3@1+ (1,0) [0|7] ""  PC
 SG_ M2P_SOC_B1 : 35|10@1+ (0.1,0) [0|102.3] "%"  PC
 SG_ M2P_SOH_B1 : 45|8@1+ (1,0) [0|255] "%"  PC
 SG_ Reserved_29 : 53|11@1+ (1,0) [0|2047] ""  PC

BO_ 2333732526 M2P_SUMDATA18__30: 8 MBMU
 SG_ M2P_SysMinVolt_B1_30 : 0|16@1+ (1,0) [0|65535] "mv"  PC
 SG_ M2P_SysAvgVolt_B1_30 : 16|16@1+ (1,0) [0|65535] "mv"  PC
 SG_ M2P_BMS_Status_B1 : 32|3@1+ (1,0) [0|7] ""  PC
 SG_ M2P_SOC_B1 : 35|10@1+ (0.1,0) [0|102.3] "%"  PC
 SG_ M2P_SOH_B1 : 45|8@1+ (1,0) [0|255] "%"  PC
 SG_ Reserved_30 : 53|11@1+ (1,0) [0|2047] ""  PC

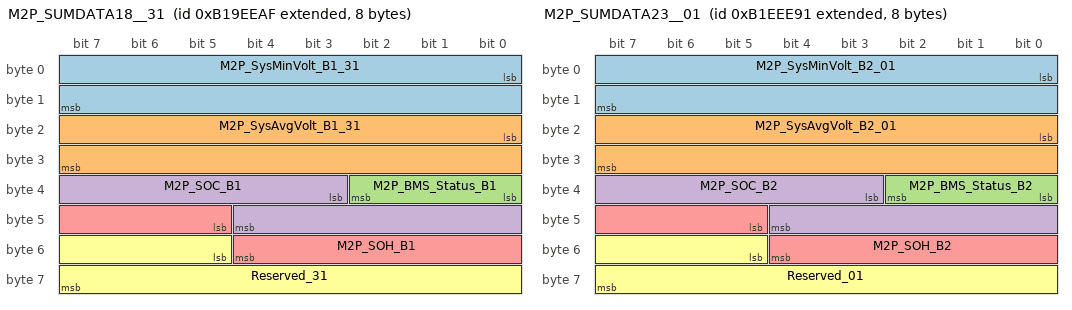
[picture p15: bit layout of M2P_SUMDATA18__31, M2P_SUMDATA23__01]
BO_ 2333732527 M2P_SUMDATA18__31: 8 MBMU
 SG_ M2P_SysMinVolt_B1_31 : 0|16@1+ (1,0) [0|65535] "mv"  PC
 SG_ M2P_SysAvgVolt_B1_31 : 16|16@1+ (1,0) [0|65535] "mv"  PC
 SG_ M2P_BMS_Status_B1 : 32|3@1+ (1,0) [0|7] ""  PC
 SG_ M2P_SOC_B1 : 35|10@1+ (0.1,0) [0|102.3] "%"  PC
 SG_ M2P_SOH_B1 : 45|8@1+ (1,0) [0|255] "%"  PC
 SG_ Reserved_31 : 53|11@1+ (1,0) [0|2047] ""  PC

BO_ 2333798033 M2P_SUMDATA19__01: 8 MBMU
 SG_ M2P_SOE_Charge_B1 : 0|10@1+ (0.1,0) [0|102.3] "%"  PC
 SG_ M2P_SOE_Discharge_B1 : 10|10@1+ (0.1,0) [0|102.3] "%"  PC
 SG_ Reserved_01 : 20|44@1+ (1,0) [0|17592186044415] ""  PC

BO_ 2333798034 M2P_SUMDATA19__02: 8 MBMU
 SG_ M2P_SOE_Charge_B1 : 0|10@1+ (0.1,0) [0|102.3] "%"  PC
 SG_ M2P_SOE_Discharge_B1 : 10|10@1+ (0.1,0) [0|102.3] "%"  PC
 SG_ Reserved_02 : 20|44@1+ (1,0) [0|17592186044415] ""  PC

BO_ 2333798035 M2P_SUMDATA19__03: 8 MBMU
 SG_ M2P_SOE_Charge_B1 : 0|10@1+ (0.1,0) [0|102.3] "%"  PC
 SG_ M2P_SOE_Discharge_B1 : 10|10@1+ (0.1,0) [0|102.3] "%"  PC
 SG_ Reserved_03 : 20|44@1+ (1,0) [0|17592186044415] ""  PC

BO_ 2333798036 M2P_SUMDATA19__04: 8 MBMU
 SG_ M2P_SOE_Charge_B1 : 0|10@1+ (0.1,0) [0|102.3] "%"  PC
 SG_ M2P_SOE_Discharge_B1 : 10|10@1+ (0.1,0) [0|102.3] "%"  PC
 SG_ Reserved_04 : 20|44@1+ (1,0) [0|17592186044415] ""  PC

BO_ 2333798037 M2P_SUMDATA19__05: 8 MBMU
 SG_ M2P_SOE_Charge_B1 : 0|10@1+ (0.1,0) [0|102.3] "%"  PC
 SG_ M2P_SOE_Discharge_B1 : 10|10@1+ (0.1,0) [0|102.3] "%"  PC
 SG_ Reserved_05 : 20|44@1+ (1,0) [0|17592186044415] ""  PC

BO_ 2333798038 M2P_SUMDATA19__06: 8 MBMU
 SG_ M2P_SOE_Charge_B1 : 0|10@1+ (0.1,0) [0|102.3] "%"  PC
 SG_ M2P_SOE_Discharge_B1 : 10|10@1+ (0.1,0) [0|102.3] "%"  PC
 SG_ Reserved_06 : 20|44@1+ (1,0) [0|17592186044415] ""  PC

BO_ 2333798039 M2P_SUMDATA19__07: 8 MBMU
 SG_ M2P_SOE_Charge_B1 : 0|10@1+ (0.1,0) [0|102.3] "%"  PC
 SG_ M2P_SOE_Discharge_B1 : 10|10@1+ (0.1,0) [0|102.3] "%"  PC
 SG_ Reserved_07 : 20|44@1+ (1,0) [0|17592186044415] ""  PC

BO_ 2333798040 M2P_SUMDATA19__08: 8 MBMU
 SG_ M2P_SOE_Charge_B1 : 0|10@1+ (0.1,0) [0|102.3] "%"  PC
 SG_ M2P_SOE_Discharge_B1 : 10|10@1+ (0.1,0) [0|102.3] "%"  PC
 SG_ Reserved_08 : 20|44@1+ (1,0) [0|17592186044415] ""  PC

BO_ 2333798041 M2P_SUMDATA19__09: 8 MBMU
 SG_ M2P_SOE_Charge_B1 : 0|10@1+ (0.1,0) [0|102.3] "%"  PC
 SG_ M2P_SOE_Discharge_B1 : 10|10@1+ (0.1,0) [0|102.3] "%"  PC
 SG_ Reserved_09 : 20|44@1+ (1,0) [0|17592186044415] ""  PC

BO_ 2333798042 M2P_SUMDATA19__10: 8 MBMU
 SG_ M2P_SOE_Charge_B1 : 0|10@1+ (0.1,0) [0|102.3] "%"  PC
 SG_ M2P_SOE_Discharge_B1 : 10|10@1+ (0.1,0) [0|102.3] "%"  PC
 SG_ Reserved_10 : 20|44@1+ (1,0) [0|17592186044415] ""  PC

BO_ 2333798043 M2P_SUMDATA19__11: 8 MBMU
 SG_ M2P_SOE_Charge_B1 : 0|10@1+ (0.1,0) [0|102.3] "%"  PC
 SG_ M2P_SOE_Discharge_B1 : 10|10@1+ (0.1,0) [0|102.3] "%"  PC
 SG_ Reserved_11 : 20|44@1+ (1,0) [0|17592186044415] ""  PC

BO_ 2333798044 M2P_SUMDATA19__12: 8 MBMU
 SG_ M2P_SOE_Charge_B1 : 0|10@1+ (0.1,0) [0|102.3] "%"  PC
 SG_ M2P_SOE_Discharge_B1 : 10|10@1+ (0.1,0) [0|102.3] "%"  PC
 SG_ Reserved_12 : 20|44@1+ (1,0) [0|17592186044415] ""  PC

BO_ 2333798045 M2P_SUMDATA19__13: 8 MBMU
 SG_ M2P_SOE_Charge_B1 : 0|10@1+ (0.1,0) [0|102.3] "%"  PC
 SG_ M2P_SOE_Discharge_B1 : 10|10@1+ (0.1,0) [0|102.3] "%"  PC
 SG_ Reserved_13 : 20|44@1+ (1,0) [0|17592186044415] ""  PC

BO_ 2333798046 M2P_SUMDATA19__14: 8 MBMU
 SG_ M2P_SOE_Charge_B1 : 0|10@1+ (0.1,0) [0|102.3] "%"  PC
 SG_ M2P_SOE_Discharge_B1 : 10|10@1+ (0.1,0) [0|102.3] "%"  PC
 SG_ Reserved_14 : 20|44@1+ (1,0) [0|17592186044415] ""  PC

BO_ 2333798047 M2P_SUMDATA19__15: 8 MBMU
 SG_ M2P_SOE_Charge_B1 : 0|10@1+ (0.1,0) [0|102.3] "%"  PC
 SG_ M2P_SOE_Discharge_B1 : 10|10@1+ (0.1,0) [0|102.3] "%"  PC
 SG_ Reserved_15 : 20|44@1+ (1,0) [0|17592186044415] ""  PC

BO_ 2333798048 M2P_SUMDATA19__16: 8 MBMU
 SG_ M2P_SOE_Charge_B1 : 0|10@1+ (0.1,0) [0|102.3] "%"  PC
 SG_ M2P_SOE_Discharge_B1 : 10|10@1+ (0.1,0) [0|102.3] "%"  PC
 SG_ Reserved_16 : 20|44@1+ (1,0) [0|17592186044415] ""  PC

BO_ 2333798049 M2P_SUMDATA19__17: 8 MBMU
 SG_ M2P_SOE_Charge_B1 : 0|10@1+ (0.1,0) [0|102.3] "%"  PC
 SG_ M2P_SOE_Discharge_B1 : 10|10@1+ (0.1,0) [0|102.3] "%"  PC
 SG_ Reserved_17 : 20|44@1+ (1,0) [0|17592186044415] ""  PC

BO_ 2333798050 M2P_SUMDATA19__18: 8 MBMU
 SG_ M2P_SOE_Charge_B1 : 0|10@1+ (0.1,0) [0|102.3] "%"  PC
 SG_ M2P_SOE_Discharge_B1 : 10|10@1+ (0.1,0) [0|102.3] "%"  PC
 SG_ Reserved_18 : 20|44@1+ (1,0) [0|17592186044415] ""  PC

BO_ 2333798051 M2P_SUMDATA19__19: 8 MBMU
 SG_ M2P_SOE_Charge_B1 : 0|10@1+ (0.1,0) [0|102.3] "%"  PC
 SG_ M2P_SOE_Discharge_B1 : 10|10@1+ (0.1,0) [0|102.3] "%"  PC
 SG_ Reserved_19 : 20|44@1+ (1,0) [0|17592186044415] ""  PC

BO_ 2333798052 M2P_SUMDATA19__20: 8 MBMU
 SG_ M2P_SOE_Charge_B1 : 0|10@1+ (0.1,0) [0|102.3] "%"  PC
 SG_ M2P_SOE_Discharge_B1 : 10|10@1+ (0.1,0) [0|102.3] "%"  PC
 SG_ Reserved_20 : 20|44@1+ (1,0) [0|17592186044415] ""  PC

BO_ 2333798053 M2P_SUMDATA19__21: 8 MBMU
 SG_ M2P_SOE_Charge_B1 : 0|10@1+ (0.1,0) [0|102.3] "%"  PC
 SG_ M2P_SOE_Discharge_B1 : 10|10@1+ (0.1,0) [0|102.3] "%"  PC
 SG_ Reserved_21 : 20|44@1+ (1,0) [0|17592186044415] ""  PC

BO_ 2333798054 M2P_SUMDATA19__22: 8 MBMU
 SG_ M2P_SOE_Charge_B1 : 0|10@1+ (0.1,0) [0|102.3] "%"  PC
 SG_ M2P_SOE_Discharge_B1 : 10|10@1+ (0.1,0) [0|102.3] "%"  PC
 SG_ Reserved_22 : 20|44@1+ (1,0) [0|17592186044415] ""  PC

BO_ 2333798055 M2P_SUMDATA19__23: 8 MBMU
 SG_ M2P_SOE_Charge_B1 : 0|10@1+ (0.1,0) [0|102.3] "%"  PC
 SG_ M2P_SOE_Discharge_B1 : 10|10@1+ (0.1,0) [0|102.3] "%"  PC
 SG_ Reserved_23 : 20|44@1+ (1,0) [0|17592186044415] ""  PC

BO_ 2333798056 M2P_SUMDATA19__24: 8 MBMU
 SG_ M2P_SOE_Charge_B1 : 0|10@1+ (0.1,0) [0|102.3] "%"  PC
 SG_ M2P_SOE_Discharge_B1 : 10|10@1+ (0.1,0) [0|102.3] "%"  PC
 SG_ Reserved_24 : 20|44@1+ (1,0) [0|17592186044415] ""  PC

BO_ 2333798057 M2P_SUMDATA19__25: 8 MBMU
 SG_ M2P_SOE_Charge_B1 : 0|10@1+ (0.1,0) [0|102.3] "%"  PC
 SG_ M2P_SOE_Discharge_B1 : 10|10@1+ (0.1,0) [0|102.3] "%"  PC
 SG_ Reserved_25 : 20|44@1+ (1,0) [0|17592186044415] ""  PC

BO_ 2333798058 M2P_SUMDATA19__26: 8 MBMU
 SG_ M2P_SOE_Charge_B1 : 0|10@1+ (0.1,0) [0|102.3] "%"  PC
 SG_ M2P_SOE_Discharge_B1 : 10|10@1+ (0.1,0) [0|102.3] "%"  PC
 SG_ Reserved_26 : 20|44@1+ (1,0) [0|17592186044415] ""  PC

BO_ 2333798059 M2P_SUMDATA19__27: 8 MBMU
 SG_ M2P_SOE_Charge_B1 : 0|10@1+ (0.1,0) [0|102.3] "%"  PC
 SG_ M2P_SOE_Discharge_B1 : 10|10@1+ (0.1,0) [0|102.3] "%"  PC
 SG_ Reserved_27 : 20|44@1+ (1,0) [0|17592186044415] ""  PC

BO_ 2333798060 M2P_SUMDATA19__28: 8 MBMU
 SG_ M2P_SOE_Charge_B1 : 0|10@1+ (0.1,0) [0|102.3] "%"  PC
 SG_ M2P_SOE_Discharge_B1 : 10|10@1+ (0.1,0) [0|102.3] "%"  PC
 SG_ Reserved_28 : 20|44@1+ (1,0) [0|17592186044415] ""  PC

BO_ 2333798061 M2P_SUMDATA19__29: 8 MBMU
 SG_ M2P_SOE_Charge_B1 : 0|10@1+ (0.1,0) [0|102.3] "%"  PC
 SG_ M2P_SOE_Discharge_B1 : 10|10@1+ (0.1,0) [0|102.3] "%"  PC
 SG_ Reserved_29 : 20|44@1+ (1,0) [0|17592186044415] ""  PC

BO_ 2333798062 M2P_SUMDATA19__30: 8 MBMU
 SG_ M2P_SOE_Charge_B1 : 0|10@1+ (0.1,0) [0|102.3] "%"  PC
 SG_ M2P_SOE_Discharge_B1 : 10|10@1+ (0.1,0) [0|102.3] "%"  PC
 SG_ Reserved_30 : 20|44@1+ (1,0) [0|17592186044415] ""  PC

BO_ 2333798063 M2P_SUMDATA19__31: 8 MBMU
 SG_ M2P_SOE_Charge_B1 : 0|10@1+ (0.1,0) [0|102.3] "%"  PC
 SG_ M2P_SOE_Discharge_B1 : 10|10@1+ (0.1,0) [0|102.3] "%"  PC
 SG_ Reserved_31 : 20|44@1+ (1,0) [0|17592186044415] ""  PC

BO_ 2333863569 M2P_SUMDATA20__01: 8 MBMU
 SG_ M2P_Measure_Vol_B2_01 : 0|16@1+ (0.1,0) [0|6553.5] "V"  PC,SBMU
 SG_ M2P_Current_B2_01 : 16|16@1+ (1,-20000) [-20000|45535] "A"  PC,SBMU
 SG_ M2P_PermitMaxCharge_I_B2_01 : 32|16@1+ (1,-20000) [-20000|45535] "A"  PC
 SG_ M2P_PermitMaxDisCharge_I_B2_01 : 48|16@1+ (1,-20000) [-20000|45535] "A"  PC

BO_ 2333863570 M2P_SUMDATA20__02: 8 MBMU
 SG_ M2P_Measure_Vol_B2_02 : 0|16@1+ (0.1,0) [0|6553.5] "V"  PC,SBMU
 SG_ M2P_Current_B2_02 : 16|16@1+ (1,-20000) [-20000|45535] "A"  PC,SBMU
 SG_ M2P_PermitMaxCharge_I_B2_02 : 32|16@1+ (1,-20000) [-20000|45535] "A"  PC
 SG_ M2P_PermitMaxDisCharge_I_B2_02 : 48|16@1+ (1,-20000) [-20000|45535] "A"  PC

BO_ 2333863571 M2P_SUMDATA20__03: 8 MBMU
 SG_ M2P_Measure_Vol_B2_03 : 0|16@1+ (0.1,0) [0|6553.5] "V"  PC,SBMU
 SG_ M2P_Current_B2_03 : 16|16@1+ (1,-20000) [-20000|45535] "A"  PC,SBMU
 SG_ M2P_PermitMaxCharge_I_B2_03 : 32|16@1+ (1,-20000) [-20000|45535] "A"  PC
 SG_ M2P_PermitMaxDisCharge_I_B2_03 : 48|16@1+ (1,-20000) [-20000|45535] "A"  PC

BO_ 2333863572 M2P_SUMDATA20__04: 8 MBMU
 SG_ M2P_Measure_Vol_B2_04 : 0|16@1+ (0.1,0) [0|6553.5] "V"  PC,SBMU
 SG_ M2P_Current_B2_04 : 16|16@1+ (1,-20000) [-20000|45535] "A"  PC,SBMU
 SG_ M2P_PermitMaxCharge_I_B2_04 : 32|16@1+ (1,-20000) [-20000|45535] "A"  PC
 SG_ M2P_PermitMaxDisCharge_I_B2_04 : 48|16@1+ (1,-20000) [-20000|45535] "A"  PC

BO_ 2333863573 M2P_SUMDATA20__05: 8 MBMU
 SG_ M2P_Measure_Vol_B2_05 : 0|16@1+ (0.1,0) [0|6553.5] "V"  PC,SBMU
 SG_ M2P_Current_B2_05 : 16|16@1+ (1,-20000) [-20000|45535] "A"  PC,SBMU
 SG_ M2P_PermitMaxCharge_I_B2_05 : 32|16@1+ (1,-20000) [-20000|45535] "A"  PC
 SG_ M2P_PermitMaxDisCharge_I_B2_05 : 48|16@1+ (1,-20000) [-20000|45535] "A"  PC

BO_ 2333863574 M2P_SUMDATA20__06: 8 MBMU
 SG_ M2P_Measure_Vol_B2_06 : 0|16@1+ (0.1,0) [0|6553.5] "V"  PC,SBMU
 SG_ M2P_Current_B2_06 : 16|16@1+ (1,-20000) [-20000|45535] "A"  PC,SBMU
 SG_ M2P_PermitMaxCharge_I_B2_06 : 32|16@1+ (1,-20000) [-20000|45535] "A"  PC
 SG_ M2P_PermitMaxDisCharge_I_B2_06 : 48|16@1+ (1,-20000) [-20000|45535] "A"  PC

BO_ 2333863575 M2P_SUMDATA20__07: 8 MBMU
 SG_ M2P_Measure_Vol_B2_07 : 0|16@1+ (0.1,0) [0|6553.5] "V"  PC,SBMU
 SG_ M2P_Current_B2_07 : 16|16@1+ (1,-20000) [-20000|45535] "A"  PC,SBMU
 SG_ M2P_PermitMaxCharge_I_B2_07 : 32|16@1+ (1,-20000) [-20000|45535] "A"  PC
 SG_ M2P_PermitMaxDisCharge_I_B2_07 : 48|16@1+ (1,-20000) [-20000|45535] "A"  PC

BO_ 2333863576 M2P_SUMDATA20__08: 8 MBMU
 SG_ M2P_Measure_Vol_B2_08 : 0|16@1+ (0.1,0) [0|6553.5] "V"  PC,SBMU
 SG_ M2P_Current_B2_08 : 16|16@1+ (1,-20000) [-20000|45535] "A"  PC,SBMU
 SG_ M2P_PermitMaxCharge_I_B2_08 : 32|16@1+ (1,-20000) [-20000|45535] "A"  PC
 SG_ M2P_PermitMaxDisCharge_I_B2_08 : 48|16@1+ (1,-20000) [-20000|45535] "A"  PC

BO_ 2333863577 M2P_SUMDATA20__09: 8 MBMU
 SG_ M2P_Measure_Vol_B2_09 : 0|16@1+ (0.1,0) [0|6553.5] "V"  PC,SBMU
 SG_ M2P_Current_B2_09 : 16|16@1+ (1,-20000) [-20000|45535] "A"  PC,SBMU
 SG_ M2P_PermitMaxCharge_I_B2_09 : 32|16@1+ (1,-20000) [-20000|45535] "A"  PC
 SG_ M2P_PermitMaxDisCharge_I_B2_09 : 48|16@1+ (1,-20000) [-20000|45535] "A"  PC

BO_ 2333863578 M2P_SUMDATA20__10: 8 MBMU
 SG_ M2P_Measure_Vol_B2_10 : 0|16@1+ (0.1,0) [0|6553.5] "V"  PC,SBMU
 SG_ M2P_Current_B2_10 : 16|16@1+ (1,-20000) [-20000|45535] "A"  PC,SBMU
 SG_ M2P_PermitMaxCharge_I_B2_10 : 32|16@1+ (1,-20000) [-20000|45535] "A"  PC
 SG_ M2P_PermitMaxDisCharge_I_B2_10 : 48|16@1+ (1,-20000) [-20000|45535] "A"  PC

BO_ 2333863579 M2P_SUMDATA20__11: 8 MBMU
 SG_ M2P_Measure_Vol_B2_11 : 0|16@1+ (0.1,0) [0|6553.5] "V"  PC,SBMU
 SG_ M2P_Current_B2_11 : 16|16@1+ (1,-20000) [-20000|45535] "A"  PC,SBMU
 SG_ M2P_PermitMaxCharge_I_B2_11 : 32|16@1+ (1,-20000) [-20000|45535] "A"  PC
 SG_ M2P_PermitMaxDisCharge_I_B2_11 : 48|16@1+ (1,-20000) [-20000|45535] "A"  PC

BO_ 2333863580 M2P_SUMDATA20__12: 8 MBMU
 SG_ M2P_Measure_Vol_B2_12 : 0|16@1+ (0.1,0) [0|6553.5] "V"  PC,SBMU
 SG_ M2P_Current_B2_12 : 16|16@1+ (1,-20000) [-20000|45535] "A"  PC,SBMU
 SG_ M2P_PermitMaxCharge_I_B2_12 : 32|16@1+ (1,-20000) [-20000|45535] "A"  PC
 SG_ M2P_PermitMaxDisCharge_I_B2_12 : 48|16@1+ (1,-20000) [-20000|45535] "A"  PC

BO_ 2333863581 M2P_SUMDATA20__13: 8 MBMU
 SG_ M2P_Measure_Vol_B2_13 : 0|16@1+ (0.1,0) [0|6553.5] "V"  PC,SBMU
 SG_ M2P_Current_B2_13 : 16|16@1+ (1,-20000) [-20000|45535] "A"  PC,SBMU
 SG_ M2P_PermitMaxCharge_I_B2_13 : 32|16@1+ (1,-20000) [-20000|45535] "A"  PC
 SG_ M2P_PermitMaxDisCharge_I_B2_13 : 48|16@1+ (1,-20000) [-20000|45535] "A"  PC

BO_ 2333863582 M2P_SUMDATA20__14: 8 MBMU
 SG_ M2P_Measure_Vol_B2_14 : 0|16@1+ (0.1,0) [0|6553.5] "V"  PC,SBMU
 SG_ M2P_Current_B2_14 : 16|16@1+ (1,-20000) [-20000|45535] "A"  PC,SBMU
 SG_ M2P_PermitMaxCharge_I_B2_14 : 32|16@1+ (1,-20000) [-20000|45535] "A"  PC
 SG_ M2P_PermitMaxDisCharge_I_B2_14 : 48|16@1+ (1,-20000) [-20000|45535] "A"  PC

BO_ 2333863583 M2P_SUMDATA20__15: 8 MBMU
 SG_ M2P_Measure_Vol_B2_15 : 0|16@1+ (0.1,0) [0|6553.5] "V"  PC,SBMU
 SG_ M2P_Current_B2_15 : 16|16@1+ (1,-20000) [-20000|45535] "A"  PC,SBMU
 SG_ M2P_PermitMaxCharge_I_B2_15 : 32|16@1+ (1,-20000) [-20000|45535] "A"  PC
 SG_ M2P_PermitMaxDisCharge_I_B2_15 : 48|16@1+ (1,-20000) [-20000|45535] "A"  PC

BO_ 2333863584 M2P_SUMDATA20__16: 8 MBMU
 SG_ M2P_Measure_Vol_B2_16 : 0|16@1+ (0.1,0) [0|6553.5] "V"  PC,SBMU
 SG_ M2P_Current_B2_16 : 16|16@1+ (1,-20000) [-20000|45535] "A"  PC,SBMU
 SG_ M2P_PermitMaxCharge_I_B2_16 : 32|16@1+ (1,-20000) [-20000|45535] "A"  PC
 SG_ M2P_PermitMaxDisCharge_I_B2_16 : 48|16@1+ (1,-20000) [-20000|45535] "A"  PC

BO_ 2333863585 M2P_SUMDATA20__17: 8 MBMU
 SG_ M2P_Measure_Vol_B2_17 : 0|16@1+ (0.1,0) [0|6553.5] "V"  PC,SBMU
 SG_ M2P_Current_B2_17 : 16|16@1+ (1,-20000) [-20000|45535] "A"  PC,SBMU
 SG_ M2P_PermitMaxCharge_I_B2_17 : 32|16@1+ (1,-20000) [-20000|45535] "A"  PC
 SG_ M2P_PermitMaxDisCharge_I_B2_17 : 48|16@1+ (1,-20000) [-20000|45535] "A"  PC

BO_ 2333863586 M2P_SUMDATA20__18: 8 MBMU
 SG_ M2P_Measure_Vol_B2_18 : 0|16@1+ (0.1,0) [0|6553.5] "V"  PC,SBMU
 SG_ M2P_Current_B2_18 : 16|16@1+ (1,-20000) [-20000|45535] "A"  PC,SBMU
 SG_ M2P_PermitMaxCharge_I_B2_18 : 32|16@1+ (1,-20000) [-20000|45535] "A"  PC
 SG_ M2P_PermitMaxDisCharge_I_B2_18 : 48|16@1+ (1,-20000) [-20000|45535] "A"  PC

BO_ 2333863587 M2P_SUMDATA20__19: 8 MBMU
 SG_ M2P_Measure_Vol_B2_19 : 0|16@1+ (0.1,0) [0|6553.5] "V"  PC,SBMU
 SG_ M2P_Current_B2_19 : 16|16@1+ (1,-20000) [-20000|45535] "A"  PC,SBMU
 SG_ M2P_PermitMaxCharge_I_B2_19 : 32|16@1+ (1,-20000) [-20000|45535] "A"  PC
 SG_ M2P_PermitMaxDisCharge_I_B2_19 : 48|16@1+ (1,-20000) [-20000|45535] "A"  PC

BO_ 2333863588 M2P_SUMDATA20__20: 8 MBMU
 SG_ M2P_Measure_Vol_B2_20 : 0|16@1+ (0.1,0) [0|6553.5] "V"  PC,SBMU
 SG_ M2P_Current_B2_20 : 16|16@1+ (1,-20000) [-20000|45535] "A"  PC,SBMU
 SG_ M2P_PermitMaxCharge_I_B2_20 : 32|16@1+ (1,-20000) [-20000|45535] "A"  PC
 SG_ M2P_PermitMaxDisCharge_I_B2_20 : 48|16@1+ (1,-20000) [-20000|45535] "A"  PC

BO_ 2333863589 M2P_SUMDATA20__21: 8 MBMU
 SG_ M2P_Measure_Vol_B2_21 : 0|16@1+ (0.1,0) [0|6553.5] "V"  PC,SBMU
 SG_ M2P_Current_B2_21 : 16|16@1+ (1,-20000) [-20000|45535] "A"  PC,SBMU
 SG_ M2P_PermitMaxCharge_I_B2_21 : 32|16@1+ (1,-20000) [-20000|45535] "A"  PC
 SG_ M2P_PermitMaxDisCharge_I_B2_21 : 48|16@1+ (1,-20000) [-20000|45535] "A"  PC

BO_ 2333863590 M2P_SUMDATA20__22: 8 MBMU
 SG_ M2P_Measure_Vol_B2_22 : 0|16@1+ (0.1,0) [0|6553.5] "V"  PC,SBMU
 SG_ M2P_Current_B2_22 : 16|16@1+ (1,-20000) [-20000|45535] "A"  PC,SBMU
 SG_ M2P_PermitMaxCharge_I_B2_22 : 32|16@1+ (1,-20000) [-20000|45535] "A"  PC
 SG_ M2P_PermitMaxDisCharge_I_B2_22 : 48|16@1+ (1,-20000) [-20000|45535] "A"  PC

BO_ 2333863591 M2P_SUMDATA20__23: 8 MBMU
 SG_ M2P_Measure_Vol_B2_23 : 0|16@1+ (0.1,0) [0|6553.5] "V"  PC,SBMU
 SG_ M2P_Current_B2_23 : 16|16@1+ (1,-20000) [-20000|45535] "A"  PC,SBMU
 SG_ M2P_PermitMaxCharge_I_B2_23 : 32|16@1+ (1,-20000) [-20000|45535] "A"  PC
 SG_ M2P_PermitMaxDisCharge_I_B2_23 : 48|16@1+ (1,-20000) [-20000|45535] "A"  PC

BO_ 2333863592 M2P_SUMDATA20__24: 8 MBMU
 SG_ M2P_Measure_Vol_B2_24 : 0|16@1+ (0.1,0) [0|6553.5] "V"  PC,SBMU
 SG_ M2P_Current_B2_24 : 16|16@1+ (1,-20000) [-20000|45535] "A"  PC,SBMU
 SG_ M2P_PermitMaxCharge_I_B2_24 : 32|16@1+ (1,-20000) [-20000|45535] "A"  PC
 SG_ M2P_PermitMaxDisCharge_I_B2_24 : 48|16@1+ (1,-20000) [-20000|45535] "A"  PC

BO_ 2333863593 M2P_SUMDATA20__25: 8 MBMU
 SG_ M2P_Measure_Vol_B2_25 : 0|16@1+ (0.1,0) [0|6553.5] "V"  PC,SBMU
 SG_ M2P_Current_B2_25 : 16|16@1+ (1,-20000) [-20000|45535] "A"  PC,SBMU
 SG_ M2P_PermitMaxCharge_I_B2_25 : 32|16@1+ (1,-20000) [-20000|45535] "A"  PC
 SG_ M2P_PermitMaxDisCharge_I_B2_25 : 48|16@1+ (1,-20000) [-20000|45535] "A"  PC

BO_ 2333863594 M2P_SUMDATA20__26: 8 MBMU
 SG_ M2P_Measure_Vol_B2_26 : 0|16@1+ (0.1,0) [0|6553.5] "V"  PC,SBMU
 SG_ M2P_Current_B2_26 : 16|16@1+ (1,-20000) [-20000|45535] "A"  PC,SBMU
 SG_ M2P_PermitMaxCharge_I_B2_26 : 32|16@1+ (1,-20000) [-20000|45535] "A"  PC
 SG_ M2P_PermitMaxDisCharge_I_B2_26 : 48|16@1+ (1,-20000) [-20000|45535] "A"  PC

BO_ 2333863595 M2P_SUMDATA20__27: 8 MBMU
 SG_ M2P_Measure_Vol_B2_27 : 0|16@1+ (0.1,0) [0|6553.5] "V"  PC,SBMU
 SG_ M2P_Current_B2_27 : 16|16@1+ (1,-20000) [-20000|45535] "A"  PC,SBMU
 SG_ M2P_PermitMaxCharge_I_B2_27 : 32|16@1+ (1,-20000) [-20000|45535] "A"  PC
 SG_ M2P_PermitMaxDisCharge_I_B2_27 : 48|16@1+ (1,-20000) [-20000|45535] "A"  PC

BO_ 2333863596 M2P_SUMDATA20__28: 8 MBMU
 SG_ M2P_Measure_Vol_B2_28 : 0|16@1+ (0.1,0) [0|6553.5] "V"  PC,SBMU
 SG_ M2P_Current_B2_28 : 16|16@1+ (1,-20000) [-20000|45535] "A"  PC,SBMU
 SG_ M2P_PermitMaxCharge_I_B2_28 : 32|16@1+ (1,-20000) [-20000|45535] "A"  PC
 SG_ M2P_PermitMaxDisCharge_I_B2_28 : 48|16@1+ (1,-20000) [-20000|45535] "A"  PC

BO_ 2333863597 M2P_SUMDATA20__29: 8 MBMU
 SG_ M2P_Measure_Vol_B2_29 : 0|16@1+ (0.1,0) [0|6553.5] "V"  PC,SBMU
 SG_ M2P_Current_B2_29 : 16|16@1+ (1,-20000) [-20000|45535] "A"  PC,SBMU
 SG_ M2P_PermitMaxCharge_I_B2_29 : 32|16@1+ (1,-20000) [-20000|45535] "A"  PC
 SG_ M2P_PermitMaxDisCharge_I_B2_29 : 48|16@1+ (1,-20000) [-20000|45535] "A"  PC

BO_ 2333863598 M2P_SUMDATA20__30: 8 MBMU
 SG_ M2P_Measure_Vol_B2_30 : 0|16@1+ (0.1,0) [0|6553.5] "V"  PC,SBMU
 SG_ M2P_Current_B2_30 : 16|16@1+ (1,-20000) [-20000|45535] "A"  PC,SBMU
 SG_ M2P_PermitMaxCharge_I_B2_30 : 32|16@1+ (1,-20000) [-20000|45535] "A"  PC
 SG_ M2P_PermitMaxDisCharge_I_B2_30 : 48|16@1+ (1,-20000) [-20000|45535] "A"  PC

BO_ 2333863599 M2P_SUMDATA20__31: 8 MBMU
 SG_ M2P_Measure_Vol_B2_31 : 0|16@1+ (0.1,0) [0|6553.5] "V"  PC,SBMU
 SG_ M2P_Current_B2_31 : 16|16@1+ (1,-20000) [-20000|45535] "A"  PC,SBMU
 SG_ M2P_PermitMaxCharge_I_B2_31 : 32|16@1+ (1,-20000) [-20000|45535] "A"  PC
 SG_ M2P_PermitMaxDisCharge_I_B2_31 : 48|16@1+ (1,-20000) [-20000|45535] "A"  PC

BO_ 2333929105 M2P_SUMDATA21__01: 8 MBMU
 SG_ M2P_PermitMaxVolt_B2_01 : 0|16@1+ (0.1,0) [0|6553.5] "V"  PC
 SG_ M2P_PermitMinVolt_B2_01 : 16|16@1+ (0.1,0) [0|6553.5] "V"  PC
 SG_ M2P_PermitMaxPow_Chg_B2_01 : 32|16@1+ (1,-20000) [-20000|45535] "Kw"  PC
 SG_ M2P_PermitMaxPow_DisChg_B2_01 : 48|16@1+ (1,-20000) [-20000|45535] "Kw"  PC

BO_ 2333929106 M2P_SUMDATA21__02: 8 MBMU
 SG_ M2P_PermitMaxVolt_B2_02 : 0|16@1+ (0.1,0) [0|6553.5] "V"  PC
 SG_ M2P_PermitMinVolt_B2_02 : 16|16@1+ (0.1,0) [0|6553.5] "V"  PC
 SG_ M2P_PermitMaxPow_Chg_B2_02 : 32|16@1+ (1,-20000) [-20000|45535] "Kw"  PC
 SG_ M2P_PermitMaxPow_DisChg_B2_02 : 48|16@1+ (1,-20000) [-20000|45535] "Kw"  PC

BO_ 2333929107 M2P_SUMDATA21__03: 8 MBMU
 SG_ M2P_PermitMaxVolt_B2_03 : 0|16@1+ (0.1,0) [0|6553.5] "V"  PC
 SG_ M2P_PermitMinVolt_B2_03 : 16|16@1+ (0.1,0) [0|6553.5] "V"  PC
 SG_ M2P_PermitMaxPow_Chg_B2_03 : 32|16@1+ (1,-20000) [-20000|45535] "Kw"  PC
 SG_ M2P_PermitMaxPow_DisChg_B2_03 : 48|16@1+ (1,-20000) [-20000|45535] "Kw"  PC

BO_ 2333929108 M2P_SUMDATA21__04: 8 MBMU
 SG_ M2P_PermitMaxVolt_B2_04 : 0|16@1+ (0.1,0) [0|6553.5] "V"  PC
 SG_ M2P_PermitMinVolt_B2_04 : 16|16@1+ (0.1,0) [0|6553.5] "V"  PC
 SG_ M2P_PermitMaxPow_Chg_B2_04 : 32|16@1+ (1,-20000) [-20000|45535] "Kw"  PC
 SG_ M2P_PermitMaxPow_DisChg_B2_04 : 48|16@1+ (1,-20000) [-20000|45535] "Kw"  PC

BO_ 2333929109 M2P_SUMDATA21__05: 8 MBMU
 SG_ M2P_PermitMaxVolt_B2_05 : 0|16@1+ (0.1,0) [0|6553.5] "V"  PC
 SG_ M2P_PermitMinVolt_B2_05 : 16|16@1+ (0.1,0) [0|6553.5] "V"  PC
 SG_ M2P_PermitMaxPow_Chg_B2_05 : 32|16@1+ (1,-20000) [-20000|45535] "Kw"  PC
 SG_ M2P_PermitMaxPow_DisChg_B2_05 : 48|16@1+ (1,-20000) [-20000|45535] "Kw"  PC

BO_ 2333929110 M2P_SUMDATA21__06: 8 MBMU
 SG_ M2P_PermitMaxVolt_B2_06 : 0|16@1+ (0.1,0) [0|6553.5] "V"  PC
 SG_ M2P_PermitMinVolt_B2_06 : 16|16@1+ (0.1,0) [0|6553.5] "V"  PC
 SG_ M2P_PermitMaxPow_Chg_B2_06 : 32|16@1+ (1,-20000) [-20000|45535] "Kw"  PC
 SG_ M2P_PermitMaxPow_DisChg_B2_06 : 48|16@1+ (1,-20000) [-20000|45535] "Kw"  PC

BO_ 2333929111 M2P_SUMDATA21__07: 8 MBMU
 SG_ M2P_PermitMaxVolt_B2_07 : 0|16@1+ (0.1,0) [0|6553.5] "V"  PC
 SG_ M2P_PermitMinVolt_B2_07 : 16|16@1+ (0.1,0) [0|6553.5] "V"  PC
 SG_ M2P_PermitMaxPow_Chg_B2_07 : 32|16@1+ (1,-20000) [-20000|45535] "Kw"  PC
 SG_ M2P_PermitMaxPow_DisChg_B2_07 : 48|16@1+ (1,-20000) [-20000|45535] "Kw"  PC

BO_ 2333929112 M2P_SUMDATA21__08: 8 MBMU
 SG_ M2P_PermitMaxVolt_B2_08 : 0|16@1+ (0.1,0) [0|6553.5] "V"  PC
 SG_ M2P_PermitMinVolt_B2_08 : 16|16@1+ (0.1,0) [0|6553.5] "V"  PC
 SG_ M2P_PermitMaxPow_Chg_B2_08 : 32|16@1+ (1,-20000) [-20000|45535] "Kw"  PC
 SG_ M2P_PermitMaxPow_DisChg_B2_08 : 48|16@1+ (1,-20000) [-20000|45535] "Kw"  PC

BO_ 2333929113 M2P_SUMDATA21__09: 8 MBMU
 SG_ M2P_PermitMaxVolt_B2_09 : 0|16@1+ (0.1,0) [0|6553.5] "V"  PC
 SG_ M2P_PermitMinVolt_B2_09 : 16|16@1+ (0.1,0) [0|6553.5] "V"  PC
 SG_ M2P_PermitMaxPow_Chg_B2_09 : 32|16@1+ (1,-20000) [-20000|45535] "Kw"  PC
 SG_ M2P_PermitMaxPow_DisChg_B2_09 : 48|16@1+ (1,-20000) [-20000|45535] "Kw"  PC

BO_ 2333929114 M2P_SUMDATA21__10: 8 MBMU
 SG_ M2P_PermitMaxVolt_B2_10 : 0|16@1+ (0.1,0) [0|6553.5] "V"  PC
 SG_ M2P_PermitMinVolt_B2_10 : 16|16@1+ (0.1,0) [0|6553.5] "V"  PC
 SG_ M2P_PermitMaxPow_Chg_B2_10 : 32|16@1+ (1,-20000) [-20000|45535] "Kw"  PC
 SG_ M2P_PermitMaxPow_DisChg_B2_10 : 48|16@1+ (1,-20000) [-20000|45535] "Kw"  PC

BO_ 2333929115 M2P_SUMDATA21__11: 8 MBMU
 SG_ M2P_PermitMaxVolt_B2_11 : 0|16@1+ (0.1,0) [0|6553.5] "V"  PC
 SG_ M2P_PermitMinVolt_B2_11 : 16|16@1+ (0.1,0) [0|6553.5] "V"  PC
 SG_ M2P_PermitMaxPow_Chg_B2_11 : 32|16@1+ (1,-20000) [-20000|45535] "Kw"  PC
 SG_ M2P_PermitMaxPow_DisChg_B2_11 : 48|16@1+ (1,-20000) [-20000|45535] "Kw"  PC

BO_ 2333929116 M2P_SUMDATA21__12: 8 MBMU
 SG_ M2P_PermitMaxVolt_B2_12 : 0|16@1+ (0.1,0) [0|6553.5] "V"  PC
 SG_ M2P_PermitMinVolt_B2_12 : 16|16@1+ (0.1,0) [0|6553.5] "V"  PC
 SG_ M2P_PermitMaxPow_Chg_B2_12 : 32|16@1+ (1,-20000) [-20000|45535] "Kw"  PC
 SG_ M2P_PermitMaxPow_DisChg_B2_12 : 48|16@1+ (1,-20000) [-20000|45535] "Kw"  PC

BO_ 2333929117 M2P_SUMDATA21__13: 8 MBMU
 SG_ M2P_PermitMaxVolt_B2_13 : 0|16@1+ (0.1,0) [0|6553.5] "V"  PC
 SG_ M2P_PermitMinVolt_B2_13 : 16|16@1+ (0.1,0) [0|6553.5] "V"  PC
 SG_ M2P_PermitMaxPow_Chg_B2_13 : 32|16@1+ (1,-20000) [-20000|45535] "Kw"  PC
 SG_ M2P_PermitMaxPow_DisChg_B2_13 : 48|16@1+ (1,-20000) [-20000|45535] "Kw"  PC

BO_ 2333929118 M2P_SUMDATA21__14: 8 MBMU
 SG_ M2P_PermitMaxVolt_B2_14 : 0|16@1+ (0.1,0) [0|6553.5] "V"  PC
 SG_ M2P_PermitMinVolt_B2_14 : 16|16@1+ (0.1,0) [0|6553.5] "V"  PC
 SG_ M2P_PermitMaxPow_Chg_B2_14 : 32|16@1+ (1,-20000) [-20000|45535] "Kw"  PC
 SG_ M2P_PermitMaxPow_DisChg_B2_14 : 48|16@1+ (1,-20000) [-20000|45535] "Kw"  PC

BO_ 2333929119 M2P_SUMDATA21__15: 8 MBMU
 SG_ M2P_PermitMaxVolt_B2_15 : 0|16@1+ (0.1,0) [0|6553.5] "V"  PC
 SG_ M2P_PermitMinVolt_B2_15 : 16|16@1+ (0.1,0) [0|6553.5] "V"  PC
 SG_ M2P_PermitMaxPow_Chg_B2_15 : 32|16@1+ (1,-20000) [-20000|45535] "Kw"  PC
 SG_ M2P_PermitMaxPow_DisChg_B2_15 : 48|16@1+ (1,-20000) [-20000|45535] "Kw"  PC

BO_ 2333929120 M2P_SUMDATA21__16: 8 MBMU
 SG_ M2P_PermitMaxVolt_B2_16 : 0|16@1+ (0.1,0) [0|6553.5] "V"  PC
 SG_ M2P_PermitMinVolt_B2_16 : 16|16@1+ (0.1,0) [0|6553.5] "V"  PC
 SG_ M2P_PermitMaxPow_Chg_B2_16 : 32|16@1+ (1,-20000) [-20000|45535] "Kw"  PC
 SG_ M2P_PermitMaxPow_DisChg_B2_16 : 48|16@1+ (1,-20000) [-20000|45535] "Kw"  PC

BO_ 2333929121 M2P_SUMDATA21__17: 8 MBMU
 SG_ M2P_PermitMaxVolt_B2_17 : 0|16@1+ (0.1,0) [0|6553.5] "V"  PC
 SG_ M2P_PermitMinVolt_B2_17 : 16|16@1+ (0.1,0) [0|6553.5] "V"  PC
 SG_ M2P_PermitMaxPow_Chg_B2_17 : 32|16@1+ (1,-20000) [-20000|45535] "Kw"  PC
 SG_ M2P_PermitMaxPow_DisChg_B2_17 : 48|16@1+ (1,-20000) [-20000|45535] "Kw"  PC

BO_ 2333929122 M2P_SUMDATA21__18: 8 MBMU
 SG_ M2P_PermitMaxVolt_B2_18 : 0|16@1+ (0.1,0) [0|6553.5] "V"  PC
 SG_ M2P_PermitMinVolt_B2_18 : 16|16@1+ (0.1,0) [0|6553.5] "V"  PC
 SG_ M2P_PermitMaxPow_Chg_B2_18 : 32|16@1+ (1,-20000) [-20000|45535] "Kw"  PC
 SG_ M2P_PermitMaxPow_DisChg_B2_18 : 48|16@1+ (1,-20000) [-20000|45535] "Kw"  PC

BO_ 2333929123 M2P_SUMDATA21__19: 8 MBMU
 SG_ M2P_PermitMaxVolt_B2_19 : 0|16@1+ (0.1,0) [0|6553.5] "V"  PC
 SG_ M2P_PermitMinVolt_B2_19 : 16|16@1+ (0.1,0) [0|6553.5] "V"  PC
 SG_ M2P_PermitMaxPow_Chg_B2_19 : 32|16@1+ (1,-20000) [-20000|45535] "Kw"  PC
 SG_ M2P_PermitMaxPow_DisChg_B2_19 : 48|16@1+ (1,-20000) [-20000|45535] "Kw"  PC

BO_ 2333929124 M2P_SUMDATA21__20: 8 MBMU
 SG_ M2P_PermitMaxVolt_B2_20 : 0|16@1+ (0.1,0) [0|6553.5] "V"  PC
 SG_ M2P_PermitMinVolt_B2_20 : 16|16@1+ (0.1,0) [0|6553.5] "V"  PC
 SG_ M2P_PermitMaxPow_Chg_B2_20 : 32|16@1+ (1,-20000) [-20000|45535] "Kw"  PC
 SG_ M2P_PermitMaxPow_DisChg_B2_20 : 48|16@1+ (1,-20000) [-20000|45535] "Kw"  PC

BO_ 2333929125 M2P_SUMDATA21__21: 8 MBMU
 SG_ M2P_PermitMaxVolt_B2_21 : 0|16@1+ (0.1,0) [0|6553.5] "V"  PC
 SG_ M2P_PermitMinVolt_B2_21 : 16|16@1+ (0.1,0) [0|6553.5] "V"  PC
 SG_ M2P_PermitMaxPow_Chg_B2_21 : 32|16@1+ (1,-20000) [-20000|45535] "Kw"  PC
 SG_ M2P_PermitMaxPow_DisChg_B2_21 : 48|16@1+ (1,-20000) [-20000|45535] "Kw"  PC

BO_ 2333929126 M2P_SUMDATA21__22: 8 MBMU
 SG_ M2P_PermitMaxVolt_B2_22 : 0|16@1+ (0.1,0) [0|6553.5] "V"  PC
 SG_ M2P_PermitMinVolt_B2_22 : 16|16@1+ (0.1,0) [0|6553.5] "V"  PC
 SG_ M2P_PermitMaxPow_Chg_B2_22 : 32|16@1+ (1,-20000) [-20000|45535] "Kw"  PC
 SG_ M2P_PermitMaxPow_DisChg_B2_22 : 48|16@1+ (1,-20000) [-20000|45535] "Kw"  PC

BO_ 2333929127 M2P_SUMDATA21__23: 8 MBMU
 SG_ M2P_PermitMaxVolt_B2_23 : 0|16@1+ (0.1,0) [0|6553.5] "V"  PC
 SG_ M2P_PermitMinVolt_B2_23 : 16|16@1+ (0.1,0) [0|6553.5] "V"  PC
 SG_ M2P_PermitMaxPow_Chg_B2_23 : 32|16@1+ (1,-20000) [-20000|45535] "Kw"  PC
 SG_ M2P_PermitMaxPow_DisChg_B2_23 : 48|16@1+ (1,-20000) [-20000|45535] "Kw"  PC

BO_ 2333929128 M2P_SUMDATA21__24: 8 MBMU
 SG_ M2P_PermitMaxVolt_B2_24 : 0|16@1+ (0.1,0) [0|6553.5] "V"  PC
 SG_ M2P_PermitMinVolt_B2_24 : 16|16@1+ (0.1,0) [0|6553.5] "V"  PC
 SG_ M2P_PermitMaxPow_Chg_B2_24 : 32|16@1+ (1,-20000) [-20000|45535] "Kw"  PC
 SG_ M2P_PermitMaxPow_DisChg_B2_24 : 48|16@1+ (1,-20000) [-20000|45535] "Kw"  PC

BO_ 2333929129 M2P_SUMDATA21__25: 8 MBMU
 SG_ M2P_PermitMaxVolt_B2_25 : 0|16@1+ (0.1,0) [0|6553.5] "V"  PC
 SG_ M2P_PermitMinVolt_B2_25 : 16|16@1+ (0.1,0) [0|6553.5] "V"  PC
 SG_ M2P_PermitMaxPow_Chg_B2_25 : 32|16@1+ (1,-20000) [-20000|45535] "Kw"  PC
 SG_ M2P_PermitMaxPow_DisChg_B2_25 : 48|16@1+ (1,-20000) [-20000|45535] "Kw"  PC

BO_ 2333929130 M2P_SUMDATA21__26: 8 MBMU
 SG_ M2P_PermitMaxVolt_B2_26 : 0|16@1+ (0.1,0) [0|6553.5] "V"  PC
 SG_ M2P_PermitMinVolt_B2_26 : 16|16@1+ (0.1,0) [0|6553.5] "V"  PC
 SG_ M2P_PermitMaxPow_Chg_B2_26 : 32|16@1+ (1,-20000) [-20000|45535] "Kw"  PC
 SG_ M2P_PermitMaxPow_DisChg_B2_26 : 48|16@1+ (1,-20000) [-20000|45535] "Kw"  PC

BO_ 2333929131 M2P_SUMDATA21__27: 8 MBMU
 SG_ M2P_PermitMaxVolt_B2_27 : 0|16@1+ (0.1,0) [0|6553.5] "V"  PC
 SG_ M2P_PermitMinVolt_B2_27 : 16|16@1+ (0.1,0) [0|6553.5] "V"  PC
 SG_ M2P_PermitMaxPow_Chg_B2_27 : 32|16@1+ (1,-20000) [-20000|45535] "Kw"  PC
 SG_ M2P_PermitMaxPow_DisChg_B2_27 : 48|16@1+ (1,-20000) [-20000|45535] "Kw"  PC

BO_ 2333929132 M2P_SUMDATA21__28: 8 MBMU
 SG_ M2P_PermitMaxVolt_B2_28 : 0|16@1+ (0.1,0) [0|6553.5] "V"  PC
 SG_ M2P_PermitMinVolt_B2_28 : 16|16@1+ (0.1,0) [0|6553.5] "V"  PC
 SG_ M2P_PermitMaxPow_Chg_B2_28 : 32|16@1+ (1,-20000) [-20000|45535] "Kw"  PC
 SG_ M2P_PermitMaxPow_DisChg_B2_28 : 48|16@1+ (1,-20000) [-20000|45535] "Kw"  PC

BO_ 2333929133 M2P_SUMDATA21__29: 8 MBMU
 SG_ M2P_PermitMaxVolt_B2_29 : 0|16@1+ (0.1,0) [0|6553.5] "V"  PC
 SG_ M2P_PermitMinVolt_B2_29 : 16|16@1+ (0.1,0) [0|6553.5] "V"  PC
 SG_ M2P_PermitMaxPow_Chg_B2_29 : 32|16@1+ (1,-20000) [-20000|45535] "Kw"  PC
 SG_ M2P_PermitMaxPow_DisChg_B2_29 : 48|16@1+ (1,-20000) [-20000|45535] "Kw"  PC

BO_ 2333929134 M2P_SUMDATA21__30: 8 MBMU
 SG_ M2P_PermitMaxVolt_B2_30 : 0|16@1+ (0.1,0) [0|6553.5] "V"  PC
 SG_ M2P_PermitMinVolt_B2_30 : 16|16@1+ (0.1,0) [0|6553.5] "V"  PC
 SG_ M2P_PermitMaxPow_Chg_B2_30 : 32|16@1+ (1,-20000) [-20000|45535] "Kw"  PC
 SG_ M2P_PermitMaxPow_DisChg_B2_30 : 48|16@1+ (1,-20000) [-20000|45535] "Kw"  PC

BO_ 2333929135 M2P_SUMDATA21__31: 8 MBMU
 SG_ M2P_PermitMaxVolt_B2_31 : 0|16@1+ (0.1,0) [0|6553.5] "V"  PC
 SG_ M2P_PermitMinVolt_B2_31 : 16|16@1+ (0.1,0) [0|6553.5] "V"  PC
 SG_ M2P_PermitMaxPow_Chg_B2_31 : 32|16@1+ (1,-20000) [-20000|45535] "Kw"  PC
 SG_ M2P_PermitMaxPow_DisChg_B2_31 : 48|16@1+ (1,-20000) [-20000|45535] "Kw"  PC

BO_ 2333994641 M2P_SUMDATA22__01: 8 MBMU
 SG_ M2P_Power_B2_01 : 0|16@1+ (1,-20000) [-20000|45535] "Kw"  PC
 SG_ M2P_SysremEngy_Chg_B2_01 : 16|16@1+ (1,0) [0|65535] "Kwh"  PC
 SG_ M2P_SysremEngy_DisChg_B2_01 : 32|16@1+ (1,0) [0|65535] "Kwh"  PC
 SG_ M2P_SysMaxVolt_B2_01 : 48|16@1+ (1,0) [0|65535] "mv"  PC

BO_ 2333994642 M2P_SUMDATA22__02: 8 MBMU
 SG_ M2P_Power_B2_02 : 0|16@1+ (1,-20000) [-20000|45535] "Kw"  PC
 SG_ M2P_SysremEngy_Chg_B2_02 : 16|16@1+ (1,0) [0|65535] "Kwh"  PC
 SG_ M2P_SysremEngy_DisChg_B2_02 : 32|16@1+ (1,0) [0|65535] "Kwh"  PC
 SG_ M2P_SysMaxVolt_B2_02 : 48|16@1+ (1,0) [0|65535] "mv"  PC

BO_ 2333994643 M2P_SUMDATA22__03: 8 MBMU
 SG_ M2P_Power_B2_03 : 0|16@1+ (1,-20000) [-20000|45535] "Kw"  PC
 SG_ M2P_SysremEngy_Chg_B2_03 : 16|16@1+ (1,0) [0|65535] "Kwh"  PC
 SG_ M2P_SysremEngy_DisChg_B2_03 : 32|16@1+ (1,0) [0|65535] "Kwh"  PC
 SG_ M2P_SysMaxVolt_B2_03 : 48|16@1+ (1,0) [0|65535] "mv"  PC

BO_ 2333994644 M2P_SUMDATA22__04: 8 MBMU
 SG_ M2P_Power_B2_04 : 0|16@1+ (1,-20000) [-20000|45535] "Kw"  PC
 SG_ M2P_SysremEngy_Chg_B2_04 : 16|16@1+ (1,0) [0|65535] "Kwh"  PC
 SG_ M2P_SysremEngy_DisChg_B2_04 : 32|16@1+ (1,0) [0|65535] "Kwh"  PC
 SG_ M2P_SysMaxVolt_B2_04 : 48|16@1+ (1,0) [0|65535] "mv"  PC

BO_ 2333994645 M2P_SUMDATA22__05: 8 MBMU
 SG_ M2P_Power_B2_05 : 0|16@1+ (1,-20000) [-20000|45535] "Kw"  PC
 SG_ M2P_SysremEngy_Chg_B2_05 : 16|16@1+ (1,0) [0|65535] "Kwh"  PC
 SG_ M2P_SysremEngy_DisChg_B2_05 : 32|16@1+ (1,0) [0|65535] "Kwh"  PC
 SG_ M2P_SysMaxVolt_B2_05 : 48|16@1+ (1,0) [0|65535] "mv"  PC

BO_ 2333994646 M2P_SUMDATA22__06: 8 MBMU
 SG_ M2P_Power_B2_06 : 0|16@1+ (1,-20000) [-20000|45535] "Kw"  PC
 SG_ M2P_SysremEngy_Chg_B2_06 : 16|16@1+ (1,0) [0|65535] "Kwh"  PC
 SG_ M2P_SysremEngy_DisChg_B2_06 : 32|16@1+ (1,0) [0|65535] "Kwh"  PC
 SG_ M2P_SysMaxVolt_B2_06 : 48|16@1+ (1,0) [0|65535] "mv"  PC

BO_ 2333994647 M2P_SUMDATA22__07: 8 MBMU
 SG_ M2P_Power_B2_07 : 0|16@1+ (1,-20000) [-20000|45535] "Kw"  PC
 SG_ M2P_SysremEngy_Chg_B2_07 : 16|16@1+ (1,0) [0|65535] "Kwh"  PC
 SG_ M2P_SysremEngy_DisChg_B2_07 : 32|16@1+ (1,0) [0|65535] "Kwh"  PC
 SG_ M2P_SysMaxVolt_B2_07 : 48|16@1+ (1,0) [0|65535] "mv"  PC

BO_ 2333994648 M2P_SUMDATA22__08: 8 MBMU
 SG_ M2P_Power_B2_08 : 0|16@1+ (1,-20000) [-20000|45535] "Kw"  PC
 SG_ M2P_SysremEngy_Chg_B2_08 : 16|16@1+ (1,0) [0|65535] "Kwh"  PC
 SG_ M2P_SysremEngy_DisChg_B2_08 : 32|16@1+ (1,0) [0|65535] "Kwh"  PC
 SG_ M2P_SysMaxVolt_B2_08 : 48|16@1+ (1,0) [0|65535] "mv"  PC

BO_ 2333994649 M2P_SUMDATA22__09: 8 MBMU
 SG_ M2P_Power_B2_09 : 0|16@1+ (1,-20000) [-20000|45535] "Kw"  PC
 SG_ M2P_SysremEngy_Chg_B2_09 : 16|16@1+ (1,0) [0|65535] "Kwh"  PC
 SG_ M2P_SysremEngy_DisChg_B2_09 : 32|16@1+ (1,0) [0|65535] "Kwh"  PC
 SG_ M2P_SysMaxVolt_B2_09 : 48|16@1+ (1,0) [0|65535] "mv"  PC

BO_ 2333994650 M2P_SUMDATA22__10: 8 MBMU
 SG_ M2P_Power_B2_10 : 0|16@1+ (1,-20000) [-20000|45535] "Kw"  PC
 SG_ M2P_SysremEngy_Chg_B2_10 : 16|16@1+ (1,0) [0|65535] "Kwh"  PC
 SG_ M2P_SysremEngy_DisChg_B2_10 : 32|16@1+ (1,0) [0|65535] "Kwh"  PC
 SG_ M2P_SysMaxVolt_B2_10 : 48|16@1+ (1,0) [0|65535] "mv"  PC

BO_ 2333994651 M2P_SUMDATA22__11: 8 MBMU
 SG_ M2P_Power_B2_11 : 0|16@1+ (1,-20000) [-20000|45535] "Kw"  PC
 SG_ M2P_SysremEngy_Chg_B2_11 : 16|16@1+ (1,0) [0|65535] "Kwh"  PC
 SG_ M2P_SysremEngy_DisChg_B2_11 : 32|16@1+ (1,0) [0|65535] "Kwh"  PC
 SG_ M2P_SysMaxVolt_B2_11 : 48|16@1+ (1,0) [0|65535] "mv"  PC

BO_ 2333994652 M2P_SUMDATA22__12: 8 MBMU
 SG_ M2P_Power_B2_12 : 0|16@1+ (1,-20000) [-20000|45535] "Kw"  PC
 SG_ M2P_SysremEngy_Chg_B2_12 : 16|16@1+ (1,0) [0|65535] "Kwh"  PC
 SG_ M2P_SysremEngy_DisChg_B2_12 : 32|16@1+ (1,0) [0|65535] "Kwh"  PC
 SG_ M2P_SysMaxVolt_B2_12 : 48|16@1+ (1,0) [0|65535] "mv"  PC

BO_ 2333994653 M2P_SUMDATA22__13: 8 MBMU
 SG_ M2P_Power_B2_13 : 0|16@1+ (1,-20000) [-20000|45535] "Kw"  PC
 SG_ M2P_SysremEngy_Chg_B2_13 : 16|16@1+ (1,0) [0|65535] "Kwh"  PC
 SG_ M2P_SysremEngy_DisChg_B2_13 : 32|16@1+ (1,0) [0|65535] "Kwh"  PC
 SG_ M2P_SysMaxVolt_B2_13 : 48|16@1+ (1,0) [0|65535] "mv"  PC

BO_ 2333994654 M2P_SUMDATA22__14: 8 MBMU
 SG_ M2P_Power_B2_14 : 0|16@1+ (1,-20000) [-20000|45535] "Kw"  PC
 SG_ M2P_SysremEngy_Chg_B2_14 : 16|16@1+ (1,0) [0|65535] "Kwh"  PC
 SG_ M2P_SysremEngy_DisChg_B2_14 : 32|16@1+ (1,0) [0|65535] "Kwh"  PC
 SG_ M2P_SysMaxVolt_B2_14 : 48|16@1+ (1,0) [0|65535] "mv"  PC

BO_ 2333994655 M2P_SUMDATA22__15: 8 MBMU
 SG_ M2P_Power_B2_15 : 0|16@1+ (1,-20000) [-20000|45535] "Kw"  PC
 SG_ M2P_SysremEngy_Chg_B2_15 : 16|16@1+ (1,0) [0|65535] "Kwh"  PC
 SG_ M2P_SysremEngy_DisChg_B2_15 : 32|16@1+ (1,0) [0|65535] "Kwh"  PC
 SG_ M2P_SysMaxVolt_B2_15 : 48|16@1+ (1,0) [0|65535] "mv"  PC

BO_ 2333994656 M2P_SUMDATA22__16: 8 MBMU
 SG_ M2P_Power_B2_16 : 0|16@1+ (1,-20000) [-20000|45535] "Kw"  PC
 SG_ M2P_SysremEngy_Chg_B2_16 : 16|16@1+ (1,0) [0|65535] "Kwh"  PC
 SG_ M2P_SysremEngy_DisChg_B2_16 : 32|16@1+ (1,0) [0|65535] "Kwh"  PC
 SG_ M2P_SysMaxVolt_B2_16 : 48|16@1+ (1,0) [0|65535] "mv"  PC

BO_ 2333994657 M2P_SUMDATA22__17: 8 MBMU
 SG_ M2P_Power_B2_17 : 0|16@1+ (1,-20000) [-20000|45535] "Kw"  PC
 SG_ M2P_SysremEngy_Chg_B2_17 : 16|16@1+ (1,0) [0|65535] "Kwh"  PC
 SG_ M2P_SysremEngy_DisChg_B2_17 : 32|16@1+ (1,0) [0|65535] "Kwh"  PC
 SG_ M2P_SysMaxVolt_B2_17 : 48|16@1+ (1,0) [0|65535] "mv"  PC

BO_ 2333994658 M2P_SUMDATA22__18: 8 MBMU
 SG_ M2P_Power_B2_18 : 0|16@1+ (1,-20000) [-20000|45535] "Kw"  PC
 SG_ M2P_SysremEngy_Chg_B2_18 : 16|16@1+ (1,0) [0|65535] "Kwh"  PC
 SG_ M2P_SysremEngy_DisChg_B2_18 : 32|16@1+ (1,0) [0|65535] "Kwh"  PC
 SG_ M2P_SysMaxVolt_B2_18 : 48|16@1+ (1,0) [0|65535] "mv"  PC

BO_ 2333994659 M2P_SUMDATA22__19: 8 MBMU
 SG_ M2P_Power_B2_19 : 0|16@1+ (1,-20000) [-20000|45535] "Kw"  PC
 SG_ M2P_SysremEngy_Chg_B2_19 : 16|16@1+ (1,0) [0|65535] "Kwh"  PC
 SG_ M2P_SysremEngy_DisChg_B2_19 : 32|16@1+ (1,0) [0|65535] "Kwh"  PC
 SG_ M2P_SysMaxVolt_B2_19 : 48|16@1+ (1,0) [0|65535] "mv"  PC

BO_ 2333994660 M2P_SUMDATA22__20: 8 MBMU
 SG_ M2P_Power_B2_20 : 0|16@1+ (1,-20000) [-20000|45535] "Kw"  PC
 SG_ M2P_SysremEngy_Chg_B2_20 : 16|16@1+ (1,0) [0|65535] "Kwh"  PC
 SG_ M2P_SysremEngy_DisChg_B2_20 : 32|16@1+ (1,0) [0|65535] "Kwh"  PC
 SG_ M2P_SysMaxVolt_B2_20 : 48|16@1+ (1,0) [0|65535] "mv"  PC

BO_ 2333994661 M2P_SUMDATA22__21: 8 MBMU
 SG_ M2P_Power_B2_21 : 0|16@1+ (1,-20000) [-20000|45535] "Kw"  PC
 SG_ M2P_SysremEngy_Chg_B2_21 : 16|16@1+ (1,0) [0|65535] "Kwh"  PC
 SG_ M2P_SysremEngy_DisChg_B2_21 : 32|16@1+ (1,0) [0|65535] "Kwh"  PC
 SG_ M2P_SysMaxVolt_B2_21 : 48|16@1+ (1,0) [0|65535] "mv"  PC

BO_ 2333994662 M2P_SUMDATA22__22: 8 MBMU
 SG_ M2P_Power_B2_22 : 0|16@1+ (1,-20000) [-20000|45535] "Kw"  PC
 SG_ M2P_SysremEngy_Chg_B2_22 : 16|16@1+ (1,0) [0|65535] "Kwh"  PC
 SG_ M2P_SysremEngy_DisChg_B2_22 : 32|16@1+ (1,0) [0|65535] "Kwh"  PC
 SG_ M2P_SysMaxVolt_B2_22 : 48|16@1+ (1,0) [0|65535] "mv"  PC

BO_ 2333994663 M2P_SUMDATA22__23: 8 MBMU
 SG_ M2P_Power_B2_23 : 0|16@1+ (1,-20000) [-20000|45535] "Kw"  PC
 SG_ M2P_SysremEngy_Chg_B2_23 : 16|16@1+ (1,0) [0|65535] "Kwh"  PC
 SG_ M2P_SysremEngy_DisChg_B2_23 : 32|16@1+ (1,0) [0|65535] "Kwh"  PC
 SG_ M2P_SysMaxVolt_B2_23 : 48|16@1+ (1,0) [0|65535] "mv"  PC

BO_ 2333994664 M2P_SUMDATA22__24: 8 MBMU
 SG_ M2P_Power_B2_24 : 0|16@1+ (1,-20000) [-20000|45535] "Kw"  PC
 SG_ M2P_SysremEngy_Chg_B2_24 : 16|16@1+ (1,0) [0|65535] "Kwh"  PC
 SG_ M2P_SysremEngy_DisChg_B2_24 : 32|16@1+ (1,0) [0|65535] "Kwh"  PC
 SG_ M2P_SysMaxVolt_B2_24 : 48|16@1+ (1,0) [0|65535] "mv"  PC

BO_ 2333994665 M2P_SUMDATA22__25: 8 MBMU
 SG_ M2P_Power_B2_25 : 0|16@1+ (1,-20000) [-20000|45535] "Kw"  PC
 SG_ M2P_SysremEngy_Chg_B2_25 : 16|16@1+ (1,0) [0|65535] "Kwh"  PC
 SG_ M2P_SysremEngy_DisChg_B2_25 : 32|16@1+ (1,0) [0|65535] "Kwh"  PC
 SG_ M2P_SysMaxVolt_B2_25 : 48|16@1+ (1,0) [0|65535] "mv"  PC

BO_ 2333994666 M2P_SUMDATA22__26: 8 MBMU
 SG_ M2P_Power_B2_26 : 0|16@1+ (1,-20000) [-20000|45535] "Kw"  PC
 SG_ M2P_SysremEngy_Chg_B2_26 : 16|16@1+ (1,0) [0|65535] "Kwh"  PC
 SG_ M2P_SysremEngy_DisChg_B2_26 : 32|16@1+ (1,0) [0|65535] "Kwh"  PC
 SG_ M2P_SysMaxVolt_B2_26 : 48|16@1+ (1,0) [0|65535] "mv"  PC

BO_ 2333994667 M2P_SUMDATA22__27: 8 MBMU
 SG_ M2P_Power_B2_27 : 0|16@1+ (1,-20000) [-20000|45535] "Kw"  PC
 SG_ M2P_SysremEngy_Chg_B2_27 : 16|16@1+ (1,0) [0|65535] "Kwh"  PC
 SG_ M2P_SysremEngy_DisChg_B2_27 : 32|16@1+ (1,0) [0|65535] "Kwh"  PC
 SG_ M2P_SysMaxVolt_B2_27 : 48|16@1+ (1,0) [0|65535] "mv"  PC

BO_ 2333994668 M2P_SUMDATA22__28: 8 MBMU
 SG_ M2P_Power_B2_28 : 0|16@1+ (1,-20000) [-20000|45535] "Kw"  PC
 SG_ M2P_SysremEngy_Chg_B2_28 : 16|16@1+ (1,0) [0|65535] "Kwh"  PC
 SG_ M2P_SysremEngy_DisChg_B2_28 : 32|16@1+ (1,0) [0|65535] "Kwh"  PC
 SG_ M2P_SysMaxVolt_B2_28 : 48|16@1+ (1,0) [0|65535] "mv"  PC

BO_ 2333994669 M2P_SUMDATA22__29: 8 MBMU
 SG_ M2P_Power_B2_29 : 0|16@1+ (1,-20000) [-20000|45535] "Kw"  PC
 SG_ M2P_SysremEngy_Chg_B2_29 : 16|16@1+ (1,0) [0|65535] "Kwh"  PC
 SG_ M2P_SysremEngy_DisChg_B2_29 : 32|16@1+ (1,0) [0|65535] "Kwh"  PC
 SG_ M2P_SysMaxVolt_B2_29 : 48|16@1+ (1,0) [0|65535] "mv"  PC

BO_ 2333994670 M2P_SUMDATA22__30: 8 MBMU
 SG_ M2P_Power_B2_30 : 0|16@1+ (1,-20000) [-20000|45535] "Kw"  PC
 SG_ M2P_SysremEngy_Chg_B2_30 : 16|16@1+ (1,0) [0|65535] "Kwh"  PC
 SG_ M2P_SysremEngy_DisChg_B2_30 : 32|16@1+ (1,0) [0|65535] "Kwh"  PC
 SG_ M2P_SysMaxVolt_B2_30 : 48|16@1+ (1,0) [0|65535] "mv"  PC

BO_ 2333994671 M2P_SUMDATA22__31: 8 MBMU
 SG_ M2P_Power_B2_31 : 0|16@1+ (1,-20000) [-20000|45535] "Kw"  PC
 SG_ M2P_SysremEngy_Chg_B2_31 : 16|16@1+ (1,0) [0|65535] "Kwh"  PC
 SG_ M2P_SysremEngy_DisChg_B2_31 : 32|16@1+ (1,0) [0|65535] "Kwh"  PC
 SG_ M2P_SysMaxVolt_B2_31 : 48|16@1+ (1,0) [0|65535] "mv"  PC

BO_ 2334060177 M2P_SUMDATA23__01: 8 MBMU
 SG_ M2P_SysMinVolt_B2_01 : 0|16@1+ (1,0) [0|65535] "mv"  PC
 SG_ M2P_SysAvgVolt_B2_01 : 16|16@1+ (1,0) [0|65535] "mv"  PC
 SG_ M2P_BMS_Status_B2 : 32|3@1+ (1,0) [0|7] ""  PC
 SG_ M2P_SOC_B2 : 35|10@1+ (0.1,0) [0|102.3] "%"  PC
 SG_ M2P_SOH_B2 : 45|8@1+ (1,0) [0|255] "%"  PC
 SG_ Reserved_01 : 53|11@1+ (1,0) [0|2047] ""  PC

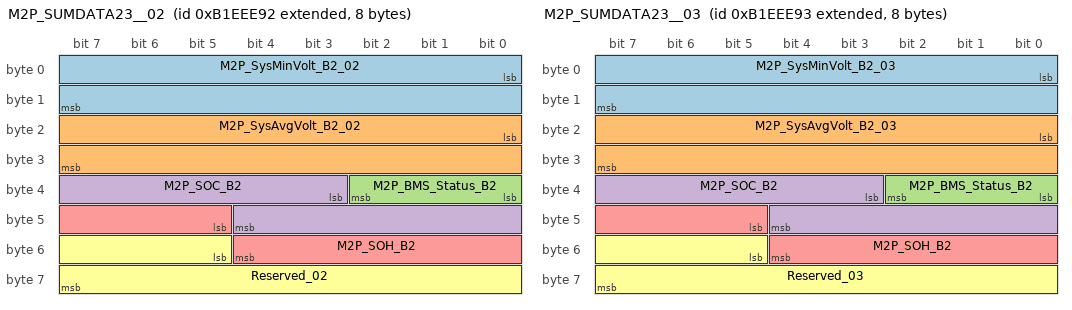
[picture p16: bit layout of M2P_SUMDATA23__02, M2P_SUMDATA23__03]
BO_ 2334060178 M2P_SUMDATA23__02: 8 MBMU
 SG_ M2P_SysMinVolt_B2_02 : 0|16@1+ (1,0) [0|65535] "mv"  PC
 SG_ M2P_SysAvgVolt_B2_02 : 16|16@1+ (1,0) [0|65535] "mv"  PC
 SG_ M2P_BMS_Status_B2 : 32|3@1+ (1,0) [0|7] ""  PC
 SG_ M2P_SOC_B2 : 35|10@1+ (0.1,0) [0|102.3] "%"  PC
 SG_ M2P_SOH_B2 : 45|8@1+ (1,0) [0|255] "%"  PC
 SG_ Reserved_02 : 53|11@1+ (1,0) [0|2047] ""  PC

BO_ 2334060179 M2P_SUMDATA23__03: 8 MBMU
 SG_ M2P_SysMinVolt_B2_03 : 0|16@1+ (1,0) [0|65535] "mv"  PC
 SG_ M2P_SysAvgVolt_B2_03 : 16|16@1+ (1,0) [0|65535] "mv"  PC
 SG_ M2P_BMS_Status_B2 : 32|3@1+ (1,0) [0|7] ""  PC
 SG_ M2P_SOC_B2 : 35|10@1+ (0.1,0) [0|102.3] "%"  PC
 SG_ M2P_SOH_B2 : 45|8@1+ (1,0) [0|255] "%"  PC
 SG_ Reserved_03 : 53|11@1+ (1,0) [0|2047] ""  PC

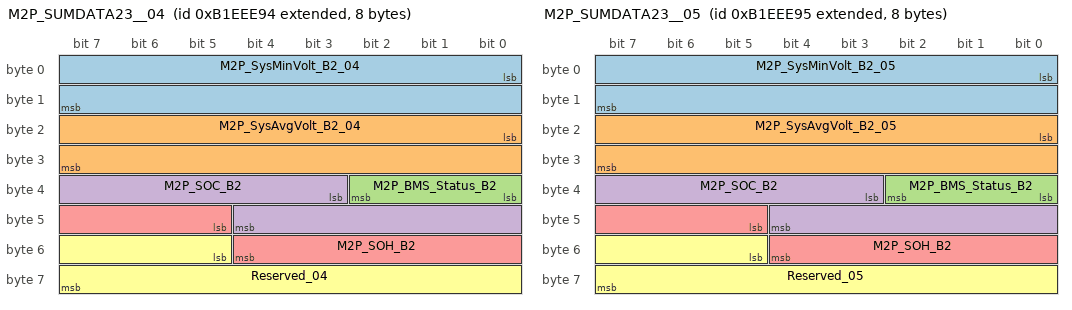
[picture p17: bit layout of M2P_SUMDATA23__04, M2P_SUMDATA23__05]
BO_ 2334060180 M2P_SUMDATA23__04: 8 MBMU
 SG_ M2P_SysMinVolt_B2_04 : 0|16@1+ (1,0) [0|65535] "mv"  PC
 SG_ M2P_SysAvgVolt_B2_04 : 16|16@1+ (1,0) [0|65535] "mv"  PC
 SG_ M2P_BMS_Status_B2 : 32|3@1+ (1,0) [0|7] ""  PC
 SG_ M2P_SOC_B2 : 35|10@1+ (0.1,0) [0|102.3] "%"  PC
 SG_ M2P_SOH_B2 : 45|8@1+ (1,0) [0|255] "%"  PC
 SG_ Reserved_04 : 53|11@1+ (1,0) [0|2047] ""  PC

BO_ 2334060181 M2P_SUMDATA23__05: 8 MBMU
 SG_ M2P_SysMinVolt_B2_05 : 0|16@1+ (1,0) [0|65535] "mv"  PC
 SG_ M2P_SysAvgVolt_B2_05 : 16|16@1+ (1,0) [0|65535] "mv"  PC
 SG_ M2P_BMS_Status_B2 : 32|3@1+ (1,0) [0|7] ""  PC
 SG_ M2P_SOC_B2 : 35|10@1+ (0.1,0) [0|102.3] "%"  PC
 SG_ M2P_SOH_B2 : 45|8@1+ (1,0) [0|255] "%"  PC
 SG_ Reserved_05 : 53|11@1+ (1,0) [0|2047] ""  PC

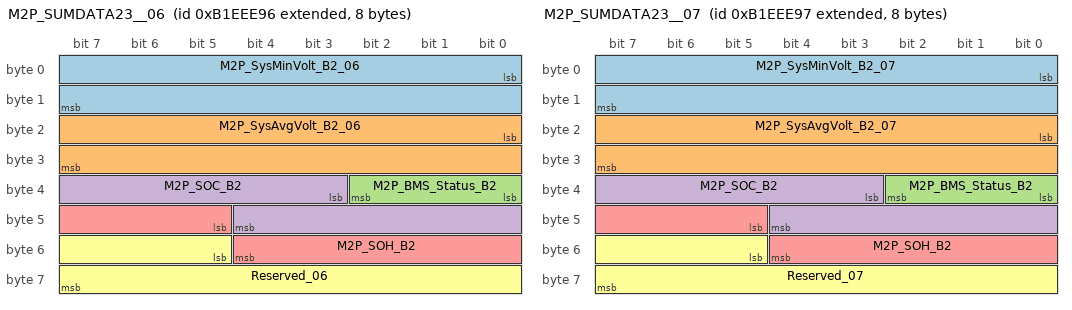
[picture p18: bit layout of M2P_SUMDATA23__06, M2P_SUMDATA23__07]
BO_ 2334060182 M2P_SUMDATA23__06: 8 MBMU
 SG_ M2P_SysMinVolt_B2_06 : 0|16@1+ (1,0) [0|65535] "mv"  PC
 SG_ M2P_SysAvgVolt_B2_06 : 16|16@1+ (1,0) [0|65535] "mv"  PC
 SG_ M2P_BMS_Status_B2 : 32|3@1+ (1,0) [0|7] ""  PC
 SG_ M2P_SOC_B2 : 35|10@1+ (0.1,0) [0|102.3] "%"  PC
 SG_ M2P_SOH_B2 : 45|8@1+ (1,0) [0|255] "%"  PC
 SG_ Reserved_06 : 53|11@1+ (1,0) [0|2047] ""  PC

BO_ 2334060183 M2P_SUMDATA23__07: 8 MBMU
 SG_ M2P_SysMinVolt_B2_07 : 0|16@1+ (1,0) [0|65535] "mv"  PC
 SG_ M2P_SysAvgVolt_B2_07 : 16|16@1+ (1,0) [0|65535] "mv"  PC
 SG_ M2P_BMS_Status_B2 : 32|3@1+ (1,0) [0|7] ""  PC
 SG_ M2P_SOC_B2 : 35|10@1+ (0.1,0) [0|102.3] "%"  PC
 SG_ M2P_SOH_B2 : 45|8@1+ (1,0) [0|255] "%"  PC
 SG_ Reserved_07 : 53|11@1+ (1,0) [0|2047] ""  PC

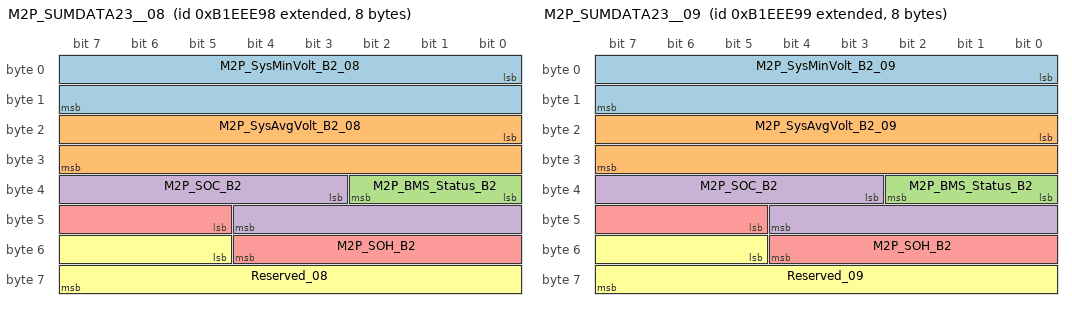
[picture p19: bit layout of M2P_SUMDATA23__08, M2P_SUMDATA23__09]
BO_ 2334060184 M2P_SUMDATA23__08: 8 MBMU
 SG_ M2P_SysMinVolt_B2_08 : 0|16@1+ (1,0) [0|65535] "mv"  PC
 SG_ M2P_SysAvgVolt_B2_08 : 16|16@1+ (1,0) [0|65535] "mv"  PC
 SG_ M2P_BMS_Status_B2 : 32|3@1+ (1,0) [0|7] ""  PC
 SG_ M2P_SOC_B2 : 35|10@1+ (0.1,0) [0|102.3] "%"  PC
 SG_ M2P_SOH_B2 : 45|8@1+ (1,0) [0|255] "%"  PC
 SG_ Reserved_08 : 53|11@1+ (1,0) [0|2047] ""  PC

BO_ 2334060185 M2P_SUMDATA23__09: 8 MBMU
 SG_ M2P_SysMinVolt_B2_09 : 0|16@1+ (1,0) [0|65535] "mv"  PC
 SG_ M2P_SysAvgVolt_B2_09 : 16|16@1+ (1,0) [0|65535] "mv"  PC
 SG_ M2P_BMS_Status_B2 : 32|3@1+ (1,0) [0|7] ""  PC
 SG_ M2P_SOC_B2 : 35|10@1+ (0.1,0) [0|102.3] "%"  PC
 SG_ M2P_SOH_B2 : 45|8@1+ (1,0) [0|255] "%"  PC
 SG_ Reserved_09 : 53|11@1+ (1,0) [0|2047] ""  PC

BO_ 2334060186 M2P_SUMDATA23__10: 8 MBMU
 SG_ M2P_SysMinVolt_B2_10 : 0|16@1+ (1,0) [0|65535] "mv"  PC
 SG_ M2P_SysAvgVolt_B2_10 : 16|16@1+ (1,0) [0|65535] "mv"  PC
 SG_ M2P_BMS_Status_B2 : 32|3@1+ (1,0) [0|7] ""  PC
 SG_ M2P_SOC_B2 : 35|10@1+ (0.1,0) [0|102.3] "%"  PC
 SG_ M2P_SOH_B2 : 45|8@1+ (1,0) [0|255] "%"  PC
 SG_ Reserved_10 : 53|11@1+ (1,0) [0|2047] ""  PC

BO_ 2334060187 M2P_SUMDATA23__11: 8 MBMU
 SG_ M2P_SysMinVolt_B2_11 : 0|16@1+ (1,0) [0|65535] "mv"  PC
 SG_ M2P_SysAvgVolt_B2_11 : 16|16@1+ (1,0) [0|65535] "mv"  PC
 SG_ M2P_BMS_Status_B2 : 32|3@1+ (1,0) [0|7] ""  PC
 SG_ M2P_SOC_B2 : 35|10@1+ (0.1,0) [0|102.3] "%"  PC
 SG_ M2P_SOH_B2 : 45|8@1+ (1,0) [0|255] "%"  PC
 SG_ Reserved_11 : 53|11@1+ (1,0) [0|2047] ""  PC

BO_ 2334060188 M2P_SUMDATA23__12: 8 MBMU
 SG_ M2P_SysMinVolt_B2_12 : 0|16@1+ (1,0) [0|65535] "mv"  PC
 SG_ M2P_SysAvgVolt_B2_12 : 16|16@1+ (1,0) [0|65535] "mv"  PC
 SG_ M2P_BMS_Status_B2 : 32|3@1+ (1,0) [0|7] ""  PC
 SG_ M2P_SOC_B2 : 35|10@1+ (0.1,0) [0|102.3] "%"  PC
 SG_ M2P_SOH_B2 : 45|8@1+ (1,0) [0|255] "%"  PC
 SG_ Reserved_12 : 53|11@1+ (1,0) [0|2047] ""  PC

BO_ 2334060189 M2P_SUMDATA23__13: 8 MBMU
 SG_ M2P_SysMinVolt_B2_13 : 0|16@1+ (1,0) [0|65535] "mv"  PC
 SG_ M2P_SysAvgVolt_B2_13 : 16|16@1+ (1,0) [0|65535] "mv"  PC
 SG_ M2P_BMS_Status_B2 : 32|3@1+ (1,0) [0|7] ""  PC
 SG_ M2P_SOC_B2 : 35|10@1+ (0.1,0) [0|102.3] "%"  PC
 SG_ M2P_SOH_B2 : 45|8@1+ (1,0) [0|255] "%"  PC
 SG_ Reserved_13 : 53|11@1+ (1,0) [0|2047] ""  PC

BO_ 2334060190 M2P_SUMDATA23__14: 8 MBMU
 SG_ M2P_SysMinVolt_B2_14 : 0|16@1+ (1,0) [0|65535] "mv"  PC
 SG_ M2P_SysAvgVolt_B2_14 : 16|16@1+ (1,0) [0|65535] "mv"  PC
 SG_ M2P_BMS_Status_B2 : 32|3@1+ (1,0) [0|7] ""  PC
 SG_ M2P_SOC_B2 : 35|10@1+ (0.1,0) [0|102.3] "%"  PC
 SG_ M2P_SOH_B2 : 45|8@1+ (1,0) [0|255] "%"  PC
 SG_ Reserved_14 : 53|11@1+ (1,0) [0|2047] ""  PC

BO_ 2334060191 M2P_SUMDATA23__15: 8 MBMU
 SG_ M2P_SysMinVolt_B2_15 : 0|16@1+ (1,0) [0|65535] "mv"  PC
 SG_ M2P_SysAvgVolt_B2_15 : 16|16@1+ (1,0) [0|65535] "mv"  PC
 SG_ M2P_BMS_Status_B2 : 32|3@1+ (1,0) [0|7] ""  PC
 SG_ M2P_SOC_B2 : 35|10@1+ (0.1,0) [0|102.3] "%"  PC
 SG_ M2P_SOH_B2 : 45|8@1+ (1,0) [0|255] "%"  PC
 SG_ Reserved_15 : 53|11@1+ (1,0) [0|2047] ""  PC

BO_ 2334060192 M2P_SUMDATA23__16: 8 MBMU
 SG_ M2P_SysMinVolt_B2_16 : 0|16@1+ (1,0) [0|65535] "mv"  PC
 SG_ M2P_SysAvgVolt_B2_16 : 16|16@1+ (1,0) [0|65535] "mv"  PC
 SG_ M2P_BMS_Status_B2 : 32|3@1+ (1,0) [0|7] ""  PC
 SG_ M2P_SOC_B2 : 35|10@1+ (0.1,0) [0|102.3] "%"  PC
 SG_ M2P_SOH_B2 : 45|8@1+ (1,0) [0|255] "%"  PC
 SG_ Reserved_16 : 53|11@1+ (1,0) [0|2047] ""  PC

BO_ 2334060193 M2P_SUMDATA23__17: 8 MBMU
 SG_ M2P_SysMinVolt_B2_17 : 0|16@1+ (1,0) [0|65535] "mv"  PC
 SG_ M2P_SysAvgVolt_B2_17 : 16|16@1+ (1,0) [0|65535] "mv"  PC
 SG_ M2P_BMS_Status_B2 : 32|3@1+ (1,0) [0|7] ""  PC
 SG_ M2P_SOC_B2 : 35|10@1+ (0.1,0) [0|102.3] "%"  PC
 SG_ M2P_SOH_B2 : 45|8@1+ (1,0) [0|255] "%"  PC
 SG_ Reserved_17 : 53|11@1+ (1,0) [0|2047] ""  PC

BO_ 2334060194 M2P_SUMDATA23__18: 8 MBMU
 SG_ M2P_SysMinVolt_B2_18 : 0|16@1+ (1,0) [0|65535] "mv"  PC
 SG_ M2P_SysAvgVolt_B2_18 : 16|16@1+ (1,0) [0|65535] "mv"  PC
 SG_ M2P_BMS_Status_B2 : 32|3@1+ (1,0) [0|7] ""  PC
 SG_ M2P_SOC_B2 : 35|10@1+ (0.1,0) [0|102.3] "%"  PC
 SG_ M2P_SOH_B2 : 45|8@1+ (1,0) [0|255] "%"  PC
 SG_ Reserved_18 : 53|11@1+ (1,0) [0|2047] ""  PC

BO_ 2334060195 M2P_SUMDATA23__19: 8 MBMU
 SG_ M2P_SysMinVolt_B2_19 : 0|16@1+ (1,0) [0|65535] "mv"  PC
 SG_ M2P_SysAvgVolt_B2_19 : 16|16@1+ (1,0) [0|65535] "mv"  PC
 SG_ M2P_BMS_Status_B2 : 32|3@1+ (1,0) [0|7] ""  PC
 SG_ M2P_SOC_B2 : 35|10@1+ (0.1,0) [0|102.3] "%"  PC
 SG_ M2P_SOH_B2 : 45|8@1+ (1,0) [0|255] "%"  PC
 SG_ Reserved_19 : 53|11@1+ (1,0) [0|2047] ""  PC

BO_ 2334060196 M2P_SUMDATA23__20: 8 MBMU
 SG_ M2P_SysMinVolt_B2_20 : 0|16@1+ (1,0) [0|65535] "mv"  PC
 SG_ M2P_SysAvgVolt_B2_20 : 16|16@1+ (1,0) [0|65535] "mv"  PC
 SG_ M2P_BMS_Status_B2 : 32|3@1+ (1,0) [0|7] ""  PC
 SG_ M2P_SOC_B2 : 35|10@1+ (0.1,0) [0|102.3] "%"  PC
 SG_ M2P_SOH_B2 : 45|8@1+ (1,0) [0|255] "%"  PC
 SG_ Reserved_20 : 53|11@1+ (1,0) [0|2047] ""  PC

BO_ 2334060197 M2P_SUMDATA23__21: 8 MBMU
 SG_ M2P_SysMinVolt_B2_21 : 0|16@1+ (1,0) [0|65535] "mv"  PC
 SG_ M2P_SysAvgVolt_B2_21 : 16|16@1+ (1,0) [0|65535] "mv"  PC
 SG_ M2P_BMS_Status_B2 : 32|3@1+ (1,0) [0|7] ""  PC
 SG_ M2P_SOC_B2 : 35|10@1+ (0.1,0) [0|102.3] "%"  PC
 SG_ M2P_SOH_B2 : 45|8@1+ (1,0) [0|255] "%"  PC
 SG_ Reserved_21 : 53|11@1+ (1,0) [0|2047] ""  PC

BO_ 2334060198 M2P_SUMDATA23__22: 8 MBMU
 SG_ M2P_SysMinVolt_B2_22 : 0|16@1+ (1,0) [0|65535] "mv"  PC
 SG_ M2P_SysAvgVolt_B2_22 : 16|16@1+ (1,0) [0|65535] "mv"  PC
 SG_ M2P_BMS_Status_B2 : 32|3@1+ (1,0) [0|7] ""  PC
 SG_ M2P_SOC_B2 : 35|10@1+ (0.1,0) [0|102.3] "%"  PC
 SG_ M2P_SOH_B2 : 45|8@1+ (1,0) [0|255] "%"  PC
 SG_ Reserved_22 : 53|11@1+ (1,0) [0|2047] ""  PC

BO_ 2334060199 M2P_SUMDATA23__23: 8 MBMU
 SG_ M2P_SysMinVolt_B2_23 : 0|16@1+ (1,0) [0|65535] "mv"  PC
 SG_ M2P_SysAvgVolt_B2_23 : 16|16@1+ (1,0) [0|65535] "mv"  PC
 SG_ M2P_BMS_Status_B2 : 32|3@1+ (1,0) [0|7] ""  PC
 SG_ M2P_SOC_B2 : 35|10@1+ (0.1,0) [0|102.3] "%"  PC
 SG_ M2P_SOH_B2 : 45|8@1+ (1,0) [0|255] "%"  PC
 SG_ Reserved_23 : 53|11@1+ (1,0) [0|2047] ""  PC

BO_ 2334060200 M2P_SUMDATA23__24: 8 MBMU
 SG_ M2P_SysMinVolt_B2_24 : 0|16@1+ (1,0) [0|65535] "mv"  PC
 SG_ M2P_SysAvgVolt_B2_24 : 16|16@1+ (1,0) [0|65535] "mv"  PC
 SG_ M2P_BMS_Status_B2 : 32|3@1+ (1,0) [0|7] ""  PC
 SG_ M2P_SOC_B2 : 35|10@1+ (0.1,0) [0|102.3] "%"  PC
 SG_ M2P_SOH_B2 : 45|8@1+ (1,0) [0|255] "%"  PC
 SG_ Reserved_24 : 53|11@1+ (1,0) [0|2047] ""  PC

BO_ 2334060201 M2P_SUMDATA23__25: 8 MBMU
 SG_ M2P_SysMinVolt_B2_25 : 0|16@1+ (1,0) [0|65535] "mv"  PC
 SG_ M2P_SysAvgVolt_B2_25 : 16|16@1+ (1,0) [0|65535] "mv"  PC
 SG_ M2P_BMS_Status_B2 : 32|3@1+ (1,0) [0|7] ""  PC
 SG_ M2P_SOC_B2 : 35|10@1+ (0.1,0) [0|102.3] "%"  PC
 SG_ M2P_SOH_B2 : 45|8@1+ (1,0) [0|255] "%"  PC
 SG_ Reserved_25 : 53|11@1+ (1,0) [0|2047] ""  PC

BO_ 2334060202 M2P_SUMDATA23__26: 8 MBMU
 SG_ M2P_SysMinVolt_B2_26 : 0|16@1+ (1,0) [0|65535] "mv"  PC
 SG_ M2P_SysAvgVolt_B2_26 : 16|16@1+ (1,0) [0|65535] "mv"  PC
 SG_ M2P_BMS_Status_B2 : 32|3@1+ (1,0) [0|7] ""  PC
 SG_ M2P_SOC_B2 : 35|10@1+ (0.1,0) [0|102.3] "%"  PC
 SG_ M2P_SOH_B2 : 45|8@1+ (1,0) [0|255] "%"  PC
 SG_ Reserved_26 : 53|11@1+ (1,0) [0|2047] ""  PC

BO_ 2334060203 M2P_SUMDATA23__27: 8 MBMU
 SG_ M2P_SysMinVolt_B2_27 : 0|16@1+ (1,0) [0|65535] "mv"  PC
 SG_ M2P_SysAvgVolt_B2_27 : 16|16@1+ (1,0) [0|65535] "mv"  PC
 SG_ M2P_BMS_Status_B2 : 32|3@1+ (1,0) [0|7] ""  PC
 SG_ M2P_SOC_B2 : 35|10@1+ (0.1,0) [0|102.3] "%"  PC
 SG_ M2P_SOH_B2 : 45|8@1+ (1,0) [0|255] "%"  PC
 SG_ Reserved_27 : 53|11@1+ (1,0) [0|2047] ""  PC

BO_ 2334060204 M2P_SUMDATA23__28: 8 MBMU
 SG_ M2P_SysMinVolt_B2_28 : 0|16@1+ (1,0) [0|65535] "mv"  PC
 SG_ M2P_SysAvgVolt_B2_28 : 16|16@1+ (1,0) [0|65535] "mv"  PC
 SG_ M2P_BMS_Status_B2 : 32|3@1+ (1,0) [0|7] ""  PC
 SG_ M2P_SOC_B2 : 35|10@1+ (0.1,0) [0|102.3] "%"  PC
 SG_ M2P_SOH_B2 : 45|8@1+ (1,0) [0|255] "%"  PC
 SG_ Reserved_28 : 53|11@1+ (1,0) [0|2047] ""  PC

BO_ 2334060205 M2P_SUMDATA23__29: 8 MBMU
 SG_ M2P_SysMinVolt_B2_29 : 0|16@1+ (1,0) [0|65535] "mv"  PC
 SG_ M2P_SysAvgVolt_B2_29 : 16|16@1+ (1,0) [0|65535] "mv"  PC
 SG_ M2P_BMS_Status_B2 : 32|3@1+ (1,0) [0|7] ""  PC
 SG_ M2P_SOC_B2 : 35|10@1+ (0.1,0) [0|102.3] "%"  PC
 SG_ M2P_SOH_B2 : 45|8@1+ (1,0) [0|255] "%"  PC
 SG_ Reserved_29 : 53|11@1+ (1,0) [0|2047] ""  PC

BO_ 2334060206 M2P_SUMDATA23__30: 8 MBMU
 SG_ M2P_SysMinVolt_B2_30 : 0|16@1+ (1,0) [0|65535] "mv"  PC
 SG_ M2P_SysAvgVolt_B2_30 : 16|16@1+ (1,0) [0|65535] "mv"  PC
 SG_ M2P_BMS_Status_B2 : 32|3@1+ (1,0) [0|7] ""  PC
 SG_ M2P_SOC_B2 : 35|10@1+ (0.1,0) [0|102.3] "%"  PC
 SG_ M2P_SOH_B2 : 45|8@1+ (1,0) [0|255] "%"  PC
 SG_ Reserved_30 : 53|11@1+ (1,0) [0|2047] ""  PC

BO_ 2334060207 M2P_SUMDATA23__31: 8 MBMU
 SG_ M2P_SysMinVolt_B2_31 : 0|16@1+ (1,0) [0|65535] "mv"  PC
 SG_ M2P_SysAvgVolt_B2_31 : 16|16@1+ (1,0) [0|65535] "mv"  PC
 SG_ M2P_BMS_Status_B2 : 32|3@1+ (1,0) [0|7] ""  PC
 SG_ M2P_SOC_B2 : 35|10@1+ (0.1,0) [0|102.3] "%"  PC
 SG_ M2P_SOH_B2 : 45|8@1+ (1,0) [0|255] "%"  PC
 SG_ Reserved_31 : 53|11@1+ (1,0) [0|2047] ""  PC

BO_ 2334125713 M2P_SUMDATA24__01: 8 MBMU
 SG_ M2P_SOE_Charge_B2 : 0|10@1+ (0.1,0) [0|102.3] "%"  PC
 SG_ M2P_SOE_Discharge_B2 : 10|10@1+ (0.1,0) [0|102.3] "%"  PC
 SG_ Reserved_01 : 20|44@1+ (1,0) [0|17592186044415] ""  PC

BO_ 2334125714 M2P_SUMDATA24__02: 8 MBMU
 SG_ M2P_SOE_Charge_B2 : 0|10@1+ (0.1,0) [0|102.3] "%"  PC
 SG_ M2P_SOE_Discharge_B2 : 10|10@1+ (0.1,0) [0|102.3] "%"  PC
 SG_ Reserved_02 : 20|44@1+ (1,0) [0|17592186044415] ""  PC

BO_ 2334125715 M2P_SUMDATA24__03: 8 MBMU
 SG_ M2P_SOE_Charge_B2 : 0|10@1+ (0.1,0) [0|102.3] "%"  PC
 SG_ M2P_SOE_Discharge_B2 : 10|10@1+ (0.1,0) [0|102.3] "%"  PC
 SG_ Reserved_03 : 20|44@1+ (1,0) [0|17592186044415] ""  PC

BO_ 2334125716 M2P_SUMDATA24__04: 8 MBMU
 SG_ M2P_SOE_Charge_B2 : 0|10@1+ (0.1,0) [0|102.3] "%"  PC
 SG_ M2P_SOE_Discharge_B2 : 10|10@1+ (0.1,0) [0|102.3] "%"  PC
 SG_ Reserved_04 : 20|44@1+ (1,0) [0|17592186044415] ""  PC

BO_ 2334125717 M2P_SUMDATA24__05: 8 MBMU
 SG_ M2P_SOE_Charge_B2 : 0|10@1+ (0.1,0) [0|102.3] "%"  PC
 SG_ M2P_SOE_Discharge_B2 : 10|10@1+ (0.1,0) [0|102.3] "%"  PC
 SG_ Reserved_05 : 20|44@1+ (1,0) [0|17592186044415] ""  PC

BO_ 2334125718 M2P_SUMDATA24__06: 8 MBMU
 SG_ M2P_SOE_Charge_B2 : 0|10@1+ (0.1,0) [0|102.3] "%"  PC
 SG_ M2P_SOE_Discharge_B2 : 10|10@1+ (0.1,0) [0|102.3] "%"  PC
 SG_ Reserved_06 : 20|44@1+ (1,0) [0|17592186044415] ""  PC

BO_ 2334125719 M2P_SUMDATA24__07: 8 MBMU
 SG_ M2P_SOE_Charge_B2 : 0|10@1+ (0.1,0) [0|102.3] "%"  PC
 SG_ M2P_SOE_Discharge_B2 : 10|10@1+ (0.1,0) [0|102.3] "%"  PC
 SG_ Reserved_07 : 20|44@1+ (1,0) [0|17592186044415] ""  PC

BO_ 2334125720 M2P_SUMDATA24__08: 8 MBMU
 SG_ M2P_SOE_Charge_B2 : 0|10@1+ (0.1,0) [0|102.3] "%"  PC
 SG_ M2P_SOE_Discharge_B2 : 10|10@1+ (0.1,0) [0|102.3] "%"  PC
 SG_ Reserved_08 : 20|44@1+ (1,0) [0|17592186044415] ""  PC

BO_ 2334125721 M2P_SUMDATA24__09: 8 MBMU
 SG_ M2P_SOE_Charge_B2 : 0|10@1+ (0.1,0) [0|102.3] "%"  PC
 SG_ M2P_SOE_Discharge_B2 : 10|10@1+ (0.1,0) [0|102.3] "%"  PC
 SG_ Reserved_09 : 20|44@1+ (1,0) [0|17592186044415] ""  PC

BO_ 2334125722 M2P_SUMDATA24__10: 8 MBMU
 SG_ M2P_SOE_Charge_B2 : 0|10@1+ (0.1,0) [0|102.3] "%"  PC
 SG_ M2P_SOE_Discharge_B2 : 10|10@1+ (0.1,0) [0|102.3] "%"  PC
 SG_ Reserved_10 : 20|44@1+ (1,0) [0|17592186044415] ""  PC

BO_ 2334125723 M2P_SUMDATA24__11: 8 MBMU
 SG_ M2P_SOE_Charge_B2 : 0|10@1+ (0.1,0) [0|102.3] "%"  PC
 SG_ M2P_SOE_Discharge_B2 : 10|10@1+ (0.1,0) [0|102.3] "%"  PC
 SG_ Reserved_11 : 20|44@1+ (1,0) [0|17592186044415] ""  PC

BO_ 2334125724 M2P_SUMDATA24__12: 8 MBMU
 SG_ M2P_SOE_Charge_B2 : 0|10@1+ (0.1,0) [0|102.3] "%"  PC
 SG_ M2P_SOE_Discharge_B2 : 10|10@1+ (0.1,0) [0|102.3] "%"  PC
 SG_ Reserved_12 : 20|44@1+ (1,0) [0|17592186044415] ""  PC

BO_ 2334125725 M2P_SUMDATA24__13: 8 MBMU
 SG_ M2P_SOE_Charge_B2 : 0|10@1+ (0.1,0) [0|102.3] "%"  PC
 SG_ M2P_SOE_Discharge_B2 : 10|10@1+ (0.1,0) [0|102.3] "%"  PC
 SG_ Reserved_13 : 20|44@1+ (1,0) [0|17592186044415] ""  PC

BO_ 2334125726 M2P_SUMDATA24__14: 8 MBMU
 SG_ M2P_SOE_Charge_B2 : 0|10@1+ (0.1,0) [0|102.3] "%"  PC
 SG_ M2P_SOE_Discharge_B2 : 10|10@1+ (0.1,0) [0|102.3] "%"  PC
 SG_ Reserved_14 : 20|44@1+ (1,0) [0|17592186044415] ""  PC

BO_ 2334125727 M2P_SUMDATA24__15: 8 MBMU
 SG_ M2P_SOE_Charge_B2 : 0|10@1+ (0.1,0) [0|102.3] "%"  PC
 SG_ M2P_SOE_Discharge_B2 : 10|10@1+ (0.1,0) [0|102.3] "%"  PC
 SG_ Reserved_15 : 20|44@1+ (1,0) [0|17592186044415] ""  PC

BO_ 2334125728 M2P_SUMDATA24__16: 8 MBMU
 SG_ M2P_SOE_Charge_B2 : 0|10@1+ (0.1,0) [0|102.3] "%"  PC
 SG_ M2P_SOE_Discharge_B2 : 10|10@1+ (0.1,0) [0|102.3] "%"  PC
 SG_ Reserved_16 : 20|44@1+ (1,0) [0|17592186044415] ""  PC

BO_ 2334125729 M2P_SUMDATA24__17: 8 MBMU
 SG_ M2P_SOE_Charge_B2 : 0|10@1+ (0.1,0) [0|102.3] "%"  PC
 SG_ M2P_SOE_Discharge_B2 : 10|10@1+ (0.1,0) [0|102.3] "%"  PC
 SG_ Reserved_17 : 20|44@1+ (1,0) [0|17592186044415] ""  PC

BO_ 2334125730 M2P_SUMDATA24__18: 8 MBMU
 SG_ M2P_SOE_Charge_B2 : 0|10@1+ (0.1,0) [0|102.3] "%"  PC
 SG_ M2P_SOE_Discharge_B2 : 10|10@1+ (0.1,0) [0|102.3] "%"  PC
 SG_ Reserved_18 : 20|44@1+ (1,0) [0|17592186044415] ""  PC

BO_ 2334125731 M2P_SUMDATA24__19: 8 MBMU
 SG_ M2P_SOE_Charge_B2 : 0|10@1+ (0.1,0) [0|102.3] "%"  PC
 SG_ M2P_SOE_Discharge_B2 : 10|10@1+ (0.1,0) [0|102.3] "%"  PC
 SG_ Reserved_19 : 20|44@1+ (1,0) [0|17592186044415] ""  PC

BO_ 2334125732 M2P_SUMDATA24__20: 8 MBMU
 SG_ M2P_SOE_Charge_B2 : 0|10@1+ (0.1,0) [0|102.3] "%"  PC
 SG_ M2P_SOE_Discharge_B2 : 10|10@1+ (0.1,0) [0|102.3] "%"  PC
 SG_ Reserved_20 : 20|44@1+ (1,0) [0|17592186044415] ""  PC

BO_ 2334125733 M2P_SUMDATA24__21: 8 MBMU
 SG_ M2P_SOE_Charge_B2 : 0|10@1+ (0.1,0) [0|102.3] "%"  PC
 SG_ M2P_SOE_Discharge_B2 : 10|10@1+ (0.1,0) [0|102.3] "%"  PC
 SG_ Reserved_21 : 20|44@1+ (1,0) [0|17592186044415] ""  PC

BO_ 2334125734 M2P_SUMDATA24__22: 8 MBMU
 SG_ M2P_SOE_Charge_B2 : 0|10@1+ (0.1,0) [0|102.3] "%"  PC
 SG_ M2P_SOE_Discharge_B2 : 10|10@1+ (0.1,0) [0|102.3] "%"  PC
 SG_ Reserved_22 : 20|44@1+ (1,0) [0|17592186044415] ""  PC

BO_ 2334125735 M2P_SUMDATA24__23: 8 MBMU
 SG_ M2P_SOE_Charge_B2 : 0|10@1+ (0.1,0) [0|102.3] "%"  PC
 SG_ M2P_SOE_Discharge_B2 : 10|10@1+ (0.1,0) [0|102.3] "%"  PC
 SG_ Reserved_23 : 20|44@1+ (1,0) [0|17592186044415] ""  PC

BO_ 2334125736 M2P_SUMDATA24__24: 8 MBMU
 SG_ M2P_SOE_Charge_B2 : 0|10@1+ (0.1,0) [0|102.3] "%"  PC
 SG_ M2P_SOE_Discharge_B2 : 10|10@1+ (0.1,0) [0|102.3] "%"  PC
 SG_ Reserved_24 : 20|44@1+ (1,0) [0|17592186044415] ""  PC

BO_ 2334125737 M2P_SUMDATA24__25: 8 MBMU
 SG_ M2P_SOE_Charge_B2 : 0|10@1+ (0.1,0) [0|102.3] "%"  PC
 SG_ M2P_SOE_Discharge_B2 : 10|10@1+ (0.1,0) [0|102.3] "%"  PC
 SG_ Reserved_25 : 20|44@1+ (1,0) [0|17592186044415] ""  PC

BO_ 2334125738 M2P_SUMDATA24__26: 8 MBMU
 SG_ M2P_SOE_Charge_B2 : 0|10@1+ (0.1,0) [0|102.3] "%"  PC
 SG_ M2P_SOE_Discharge_B2 : 10|10@1+ (0.1,0) [0|102.3] "%"  PC
 SG_ Reserved_26 : 20|44@1+ (1,0) [0|17592186044415] ""  PC

BO_ 2334125739 M2P_SUMDATA24__27: 8 MBMU
 SG_ M2P_SOE_Charge_B2 : 0|10@1+ (0.1,0) [0|102.3] "%"  PC
 SG_ M2P_SOE_Discharge_B2 : 10|10@1+ (0.1,0) [0|102.3] "%"  PC
 SG_ Reserved_27 : 20|44@1+ (1,0) [0|17592186044415] ""  PC

BO_ 2334125740 M2P_SUMDATA24__28: 8 MBMU
 SG_ M2P_SOE_Charge_B2 : 0|10@1+ (0.1,0) [0|102.3] "%"  PC
 SG_ M2P_SOE_Discharge_B2 : 10|10@1+ (0.1,0) [0|102.3] "%"  PC
 SG_ Reserved_28 : 20|44@1+ (1,0) [0|17592186044415] ""  PC

BO_ 2334125741 M2P_SUMDATA24__29: 8 MBMU
 SG_ M2P_SOE_Charge_B2 : 0|10@1+ (0.1,0) [0|102.3] "%"  PC
 SG_ M2P_SOE_Discharge_B2 : 10|10@1+ (0.1,0) [0|102.3] "%"  PC
 SG_ Reserved_29 : 20|44@1+ (1,0) [0|17592186044415] ""  PC

BO_ 2334125742 M2P_SUMDATA24__30: 8 MBMU
 SG_ M2P_SOE_Charge_B2 : 0|10@1+ (0.1,0) [0|102.3] "%"  PC
 SG_ M2P_SOE_Discharge_B2 : 10|10@1+ (0.1,0) [0|102.3] "%"  PC
 SG_ Reserved_30 : 20|44@1+ (1,0) [0|17592186044415] ""  PC

BO_ 2334125743 M2P_SUMDATA24__31: 8 MBMU
 SG_ M2P_SOE_Charge_B2 : 0|10@1+ (0.1,0) [0|102.3] "%"  PC
 SG_ M2P_SOE_Discharge_B2 : 10|10@1+ (0.1,0) [0|102.3] "%"  PC
 SG_ Reserved_31 : 20|44@1+ (1,0) [0|17592186044415] ""  PC

CM_ SG_ 2333535917 M2P_Measure_Vol_B1_29 "汇流排1所有高压在线电柜外侧电压平均值    ";
CM_ SG_ 2333535917 M2P_Current_B1_29 "汇流排1所有电柜电流累加和";
CM_ SG_ 2333535917 M2P_PermitMaxCharge_I_B1_29 "汇流排1最大允许充电电流";
CM_ SG_ 2333535917 M2P_PermitMaxDisCharge_I_B1_29 "汇流排1最大允许放电电流";
CM_ SG_ 2333535918 M2P_Measure_Vol_B1_30 "汇流排1所有高压在线电柜外侧电压平均值    ";
CM_ SG_ 2333535918 M2P_Current_B1_30 "汇流排1所有电柜电流累加和";
CM_ SG_ 2333535918 M2P_PermitMaxCharge_I_B1_30 "汇流排1最大允许充电电流";
CM_ SG_ 2333535918 M2P_PermitMaxDisCharge_I_B1_30 "汇流排1最大允许放电电流";
CM_ SG_ 2333535919 M2P_Measure_Vol_B1_31 "汇流排1所有高压在线电柜外侧电压平均值    ";
CM_ SG_ 2333535919 M2P_Current_B1_31 "汇流排1所有电柜电流累加和";
CM_ SG_ 2333535919 M2P_PermitMaxCharge_I_B1_31 "汇流排1最大允许充电电流";
CM_ SG_ 2333535919 M2P_PermitMaxDisCharge_I_B1_31 "汇流排1最大允许放电电流";
CM_ SG_ 2333601425 M2P_PermitMaxVolt_B1_01 "汇流排1最高允许充电电压 （配置量）";
CM_ SG_ 2333601425 M2P_PermitMinVolt_B1_01 "汇流排1最低允许放电电压 （配置量）";
CM_ SG_ 2333601425 M2P_PermitMaxPow_Chg_B1_01 "汇流排1最大允许充电功率";
CM_ SG_ 2333601425 M2P_PermitMaxPow_DisChg_B1_01 "汇流排1最大允许放电功率";
CM_ SG_ 2333601426 M2P_PermitMaxVolt_B1_02 "汇流排1最高允许充电电压 （配置量）";
CM_ SG_ 2333601426 M2P_PermitMinVolt_B1_02 "汇流排1最低允许放电电压 （配置量）";
CM_ SG_ 2333601426 M2P_PermitMaxPow_Chg_B1_02 "汇流排1最大允许充电功率";
CM_ SG_ 2333601426 M2P_PermitMaxPow_DisChg_B1_02 "汇流排1最大允许放电功率";
CM_ SG_ 2333601427 M2P_PermitMaxVolt_B1_03 "汇流排1最高允许充电电压 （配置量）";
CM_ SG_ 2333601427 M2P_PermitMinVolt_B1_03 "汇流排1最低允许放电电压 （配置量）";
CM_ SG_ 2333601427 M2P_PermitMaxPow_Chg_B1_03 "汇流排1最大允许充电功率";
CM_ SG_ 2333601427 M2P_PermitMaxPow_DisChg_B1_03 "汇流排1最大允许放电功率";
CM_ SG_ 2333601428 M2P_PermitMaxVolt_B1_04 "汇流排1最高允许充电电压 （配置量）";
CM_ SG_ 2333601428 M2P_PermitMinVolt_B1_04 "汇流排1最低允许放电电压 （配置量）";
CM_ SG_ 2333601428 M2P_PermitMaxPow_Chg_B1_04 "汇流排1最大允许充电功率";
CM_ SG_ 2333601428 M2P_PermitMaxPow_DisChg_B1_04 "汇流排1最大允许放电功率";
CM_ SG_ 2333601429 M2P_PermitMaxVolt_B1_05 "汇流排1最高允许充电电压 （配置量）";
CM_ SG_ 2333601429 M2P_PermitMinVolt_B1_05 "汇流排1最低允许放电电压 （配置量）";
CM_ SG_ 2333601429 M2P_PermitMaxPow_Chg_B1_05 "汇流排1最大允许充电功率";
CM_ SG_ 2333601429 M2P_PermitMaxPow_DisChg_B1_05 "汇流排1最大允许放电功率";
CM_ SG_ 2333601430 M2P_PermitMaxVolt_B1_06 "汇流排1最高允许充电电压 （配置量）";
CM_ SG_ 2333601430 M2P_PermitMinVolt_B1_06 "汇流排1最低允许放电电压 （配置量）";
CM_ SG_ 2333601430 M2P_PermitMaxPow_Chg_B1_06 "汇流排1最大允许充电功率";
CM_ SG_ 2333601430 M2P_PermitMaxPow_DisChg_B1_06 "汇流排1最大允许放电功率";
CM_ SG_ 2333601431 M2P_PermitMaxVolt_B1_07 "汇流排1最高允许充电电压 （配置量）";
CM_ SG_ 2333601431 M2P_PermitMinVolt_B1_07 "汇流排1最低允许放电电压 （配置量）";
CM_ SG_ 2333601431 M2P_PermitMaxPow_Chg_B1_07 "汇流排1最大允许充电功率";
CM_ SG_ 2333601431 M2P_PermitMaxPow_DisChg_B1_07 "汇流排1最大允许放电功率";
CM_ SG_ 2333601432 M2P_PermitMaxVolt_B1_08 "汇流排1最高允许充电电压 （配置量）";
CM_ SG_ 2333601432 M2P_PermitMinVolt_B1_08 "汇流排1最低允许放电电压 （配置量）";
CM_ SG_ 2333601432 M2P_PermitMaxPow_Chg_B1_08 "汇流排1最大允许充电功率";
CM_ SG_ 2333601432 M2P_PermitMaxPow_DisChg_B1_08 "汇流排1最大允许放电功率";
CM_ SG_ 2333601433 M2P_PermitMaxVolt_B1_09 "汇流排1最高允许充电电压 （配置量）";
CM_ SG_ 2333601433 M2P_PermitMinVolt_B1_09 "汇流排1最低允许放电电压 （配置量）";
CM_ SG_ 2333601433 M2P_PermitMaxPow_Chg_B1_09 "汇流排1最大允许充电功率";
CM_ SG_ 2333601433 M2P_PermitMaxPow_DisChg_B1_09 "汇流排1最大允许放电功率";
CM_ SG_ 2333601434 M2P_PermitMaxVolt_B1_10 "汇流排1最高允许充电电压 （配置量）";
CM_ SG_ 2333601434 M2P_PermitMinVolt_B1_10 "汇流排1最低允许放电电压 （配置量）";
CM_ SG_ 2333601434 M2P_PermitMaxPow_Chg_B1_10 "汇流排1最大允许充电功率";
CM_ SG_ 2333601434 M2P_PermitMaxPow_DisChg_B1_10 "汇流排1最大允许放电功率";
CM_ SG_ 2333601435 M2P_PermitMaxVolt_B1_11 "汇流排1最高允许充电电压 （配置量）";
CM_ SG_ 2333601435 M2P_PermitMinVolt_B1_11 "汇流排1最低允许放电电压 （配置量）";
CM_ SG_ 2333601435 M2P_PermitMaxPow_Chg_B1_11 "汇流排1最大允许充电功率";
CM_ SG_ 2333601435 M2P_PermitMaxPow_DisChg_B1_11 "汇流排1最大允许放电功率";
CM_ SG_ 2333601436 M2P_PermitMaxVolt_B1_12 "汇流排1最高允许充电电压 （配置量）";
CM_ SG_ 2333601436 M2P_PermitMinVolt_B1_12 "汇流排1最低允许放电电压 （配置量）";
CM_ SG_ 2333601436 M2P_PermitMaxPow_Chg_B1_12 "汇流排1最大允许充电功率";
CM_ SG_ 2333601436 M2P_PermitMaxPow_DisChg_B1_12 "汇流排1最大允许放电功率";
CM_ SG_ 2333601437 M2P_PermitMaxVolt_B1_13 "汇流排1最高允许充电电压 （配置量）";
CM_ SG_ 2333601437 M2P_PermitMinVolt_B1_13 "汇流排1最低允许放电电压 （配置量）";
CM_ SG_ 2333601437 M2P_PermitMaxPow_Chg_B1_13 "汇流排1最大允许充电功率";
CM_ SG_ 2333601437 M2P_PermitMaxPow_DisChg_B1_13 "汇流排1最大允许放电功率";
CM_ SG_ 2333601438 M2P_PermitMaxVolt_B1_14 "汇流排1最高允许充电电压 （配置量）";
CM_ SG_ 2333601438 M2P_PermitMinVolt_B1_14 "汇流排1最低允许放电电压 （配置量）";
CM_ SG_ 2333601438 M2P_PermitMaxPow_Chg_B1_14 "汇流排1最大允许充电功率";
CM_ SG_ 2333601438 M2P_PermitMaxPow_DisChg_B1_14 "汇流排1最大允许放电功率";
CM_ SG_ 2333601439 M2P_PermitMaxVolt_B1_15 "汇流排1最高允许充电电压 （配置量）";
CM_ SG_ 2333601439 M2P_PermitMinVolt_B1_15 "汇流排1最低允许放电电压 （配置量）";
CM_ SG_ 2333601439 M2P_PermitMaxPow_Chg_B1_15 "汇流排1最大允许充电功率";
CM_ SG_ 2333601439 M2P_PermitMaxPow_DisChg_B1_15 "汇流排1最大允许放电功率";
CM_ SG_ 2333601440 M2P_PermitMaxVolt_B1_16 "汇流排1最高允许充电电压 （配置量）";
CM_ SG_ 2333601440 M2P_PermitMinVolt_B1_16 "汇流排1最低允许放电电压 （配置量）";
CM_ SG_ 2333601440 M2P_PermitMaxPow_Chg_B1_16 "汇流排1最大允许充电功率";
CM_ SG_ 2333601440 M2P_PermitMaxPow_DisChg_B1_16 "汇流排1最大允许放电功率";
CM_ SG_ 2333601441 M2P_PermitMaxVolt_B1_17 "汇流排1最高允许充电电压 （配置量）";
CM_ SG_ 2333601441 M2P_PermitMinVolt_B1_17 "汇流排1最低允许放电电压 （配置量）";
CM_ SG_ 2333601441 M2P_PermitMaxPow_Chg_B1_17 "汇流排1最大允许充电功率";
CM_ SG_ 2333601441 M2P_PermitMaxPow_DisChg_B1_17 "汇流排1最大允许放电功率";
CM_ SG_ 2333601442 M2P_PermitMaxVolt_B1_18 "汇流排1最高允许充电电压 （配置量）";
CM_ SG_ 2333601442 M2P_PermitMinVolt_B1_18 "汇流排1最低允许放电电压 （配置量）";
CM_ SG_ 2333601442 M2P_PermitMaxPow_Chg_B1_18 "汇流排1最大允许充电功率";
CM_ SG_ 2333601442 M2P_PermitMaxPow_DisChg_B1_18 "汇流排1最大允许放电功率";
CM_ SG_ 2333601443 M2P_PermitMaxVolt_B1_19 "汇流排1最高允许充电电压 （配置量）";
CM_ SG_ 2333601443 M2P_PermitMinVolt_B1_19 "汇流排1最低允许放电电压 （配置量）";
CM_ SG_ 2333601443 M2P_PermitMaxPow_Chg_B1_19 "汇流排1最大允许充电功率";
CM_ SG_ 2333601443 M2P_PermitMaxPow_DisChg_B1_19 "汇流排1最大允许放电功率";
CM_ SG_ 2333601444 M2P_PermitMaxVolt_B1_20 "汇流排1最高允许充电电压 （配置量）";
CM_ SG_ 2333601444 M2P_PermitMinVolt_B1_20 "汇流排1最低允许放电电压 （配置量）";
CM_ SG_ 2333601444 M2P_PermitMaxPow_Chg_B1_20 "汇流排1最大允许充电功率";
CM_ SG_ 2333601444 M2P_PermitMaxPow_DisChg_B1_20 "汇流排1最大允许放电功率";
CM_ SG_ 2333601445 M2P_PermitMaxVolt_B1_21 "汇流排1最高允许充电电压 （配置量）";
CM_ SG_ 2333601445 M2P_PermitMinVolt_B1_21 "汇流排1最低允许放电电压 （配置量）";
CM_ SG_ 2333601445 M2P_PermitMaxPow_Chg_B1_21 "汇流排1最大允许充电功率";
CM_ SG_ 2333601445 M2P_PermitMaxPow_DisChg_B1_21 "汇流排1最大允许放电功率";
CM_ SG_ 2333601446 M2P_PermitMaxVolt_B1_22 "汇流排1最高允许充电电压 （配置量）";
CM_ SG_ 2333601446 M2P_PermitMinVolt_B1_22 "汇流排1最低允许放电电压 （配置量）";
CM_ SG_ 2333601446 M2P_PermitMaxPow_Chg_B1_22 "汇流排1最大允许充电功率";
CM_ SG_ 2333601446 M2P_PermitMaxPow_DisChg_B1_22 "汇流排1最大允许放电功率";
CM_ SG_ 2333601447 M2P_PermitMaxVolt_B1_23 "汇流排1最高允许充电电压 （配置量）";
CM_ SG_ 2333601447 M2P_PermitMinVolt_B1_23 "汇流排1最低允许放电电压 （配置量）";
CM_ SG_ 2333601447 M2P_PermitMaxPow_Chg_B1_23 "汇流排1最大允许充电功率";
CM_ SG_ 2333601447 M2P_PermitMaxPow_DisChg_B1_23 "汇流排1最大允许放电功率";
CM_ SG_ 2333601448 M2P_PermitMaxVolt_B1_24 "汇流排1最高允许充电电压 （配置量）";
CM_ SG_ 2333601448 M2P_PermitMinVolt_B1_24 "汇流排1最低允许放电电压 （配置量）";
CM_ SG_ 2333601448 M2P_PermitMaxPow_Chg_B1_24 "汇流排1最大允许充电功率";
CM_ SG_ 2333601448 M2P_PermitMaxPow_DisChg_B1_24 "汇流排1最大允许放电功率";
CM_ SG_ 2333601449 M2P_PermitMaxVolt_B1_25 "汇流排1最高允许充电电压 （配置量）";
CM_ SG_ 2333601449 M2P_PermitMinVolt_B1_25 "汇流排1最低允许放电电压 （配置量）";
CM_ SG_ 2333601449 M2P_PermitMaxPow_Chg_B1_25 "汇流排1最大允许充电功率";
CM_ SG_ 2333601449 M2P_PermitMaxPow_DisChg_B1_25 "汇流排1最大允许放电功率";
CM_ SG_ 2333601450 M2P_PermitMaxVolt_B1_26 "汇流排1最高允许充电电压 （配置量）";
CM_ SG_ 2333601450 M2P_PermitMinVolt_B1_26 "汇流排1最低允许放电电压 （配置量）";
CM_ SG_ 2333601450 M2P_PermitMaxPow_Chg_B1_26 "汇流排1最大允许充电功率";
CM_ SG_ 2333601450 M2P_PermitMaxPow_DisChg_B1_26 "汇流排1最大允许放电功率";
CM_ SG_ 2333601451 M2P_PermitMaxVolt_B1_27 "汇流排1最高允许充电电压 （配置量）";
CM_ SG_ 2333601451 M2P_PermitMinVolt_B1_27 "汇流排1最低允许放电电压 （配置量）";
CM_ SG_ 2333601451 M2P_PermitMaxPow_Chg_B1_27 "汇流排1最大允许充电功率";
CM_ SG_ 2333601451 M2P_PermitMaxPow_DisChg_B1_27 "汇流排1最大允许放电功率";
CM_ SG_ 2333601452 M2P_PermitMaxVolt_B1_28 "汇流排1最高允许充电电压 （配置量）";
CM_ SG_ 2333601452 M2P_PermitMinVolt_B1_28 "汇流排1最低允许放电电压 （配置量）";
CM_ SG_ 2333601452 M2P_PermitMaxPow_Chg_B1_28 "汇流排1最大允许充电功率";
CM_ SG_ 2333601452 M2P_PermitMaxPow_DisChg_B1_28 "汇流排1最大允许放电功率";
CM_ SG_ 2333601453 M2P_PermitMaxVolt_B1_29 "汇流排1最高允许充电电压 （配置量）";
CM_ SG_ 2333601453 M2P_PermitMinVolt_B1_29 "汇流排1最低允许放电电压 （配置量）";
CM_ SG_ 2333601453 M2P_PermitMaxPow_Chg_B1_29 "汇流排1最大允许充电功率";
CM_ SG_ 2333601453 M2P_PermitMaxPow_DisChg_B1_29 "汇流排1最大允许放电功率";
CM_ SG_ 2333601454 M2P_PermitMaxVolt_B1_30 "汇流排1最高允许充电电压 （配置量）";
CM_ SG_ 2333601454 M2P_PermitMinVolt_B1_30 "汇流排1最低允许放电电压 （配置量）";
CM_ SG_ 2333601454 M2P_PermitMaxPow_Chg_B1_30 "汇流排1最大允许充电功率";
CM_ SG_ 2333601454 M2P_PermitMaxPow_DisChg_B1_30 "汇流排1最大允许放电功率";
CM_ SG_ 2333601455 M2P_PermitMaxVolt_B1_31 "汇流排1最高允许充电电压 （配置量）";
CM_ SG_ 2333601455 M2P_PermitMinVolt_B1_31 "汇流排1最低允许放电电压 （配置量）";
CM_ SG_ 2333601455 M2P_PermitMaxPow_Chg_B1_31 "汇流排1最大允许充电功率";
CM_ SG_ 2333601455 M2P_PermitMaxPow_DisChg_B1_31 "汇流排1最大允许放电功率";
CM_ SG_ 2333666961 M2P_Power_B1_01 "汇流排1实时功率";
CM_ SG_ 2333666961 M2P_SysremEngy_Chg_B1_01 "汇流排1充电剩余能量";
CM_ SG_ 2333666961 M2P_SysremEngy_DisChg_B1_01 "汇流排1放电剩余能量";
CM_ SG_ 2333666961 M2P_SysMaxVolt_B1_01 "汇流排1单体最大电压  ";
CM_ SG_ 2333666962 M2P_Power_B1_02 "汇流排1实时功率";
CM_ SG_ 2333666962 M2P_SysremEngy_Chg_B1_02 "汇流排1充电剩余能量";
CM_ SG_ 2333666962 M2P_SysremEngy_DisChg_B1_02 "汇流排1放电剩余能量";
CM_ SG_ 2333666962 M2P_SysMaxVolt_B1_02 "汇流排1单体最大电压  ";
CM_ SG_ 2333666963 M2P_Power_B1_03 "汇流排1实时功率";
CM_ SG_ 2333666963 M2P_SysremEngy_Chg_B1_03 "汇流排1充电剩余能量";
CM_ SG_ 2333666963 M2P_SysremEngy_DisChg_B1_03 "汇流排1放电剩余能量";
CM_ SG_ 2333666963 M2P_SysMaxVolt_B1_03 "汇流排1单体最大电压  ";
CM_ SG_ 2333666964 M2P_Power_B1_04 "汇流排1实时功率";
CM_ SG_ 2333666964 M2P_SysremEngy_Chg_B1_04 "汇流排1充电剩余能量";
CM_ SG_ 2333666964 M2P_SysremEngy_DisChg_B1_04 "汇流排1放电剩余能量";
CM_ SG_ 2333666964 M2P_SysMaxVolt_B1_04 "汇流排1单体最大电压  ";
CM_ SG_ 2333666965 M2P_Power_B1_05 "汇流排1实时功率";
CM_ SG_ 2333666965 M2P_SysremEngy_Chg_B1_05 "汇流排1充电剩余能量";
CM_ SG_ 2333666965 M2P_SysremEngy_DisChg_B1_05 "汇流排1放电剩余能量";
CM_ SG_ 2333666965 M2P_SysMaxVolt_B1_05 "汇流排1单体最大电压  ";
CM_ SG_ 2333666966 M2P_Power_B1_06 "汇流排1实时功率";
CM_ SG_ 2333666966 M2P_SysremEngy_Chg_B1_06 "汇流排1充电剩余能量";
CM_ SG_ 2333666966 M2P_SysremEngy_DisChg_B1_06 "汇流排1放电剩余能量";
CM_ SG_ 2333666966 M2P_SysMaxVolt_B1_06 "汇流排1单体最大电压  ";
CM_ SG_ 2333666967 M2P_Power_B1_07 "汇流排1实时功率";
CM_ SG_ 2333666967 M2P_SysremEngy_Chg_B1_07 "汇流排1充电剩余能量";
CM_ SG_ 2333666967 M2P_SysremEngy_DisChg_B1_07 "汇流排1放电剩余能量";
CM_ SG_ 2333666967 M2P_SysMaxVolt_B1_07 "汇流排1单体最大电压  ";
CM_ SG_ 2333666968 M2P_Power_B1_08 "汇流排1实时功率";
CM_ SG_ 2333666968 M2P_SysremEngy_Chg_B1_08 "汇流排1充电剩余能量";
CM_ SG_ 2333666968 M2P_SysremEngy_DisChg_B1_08 "汇流排1放电剩余能量";
CM_ SG_ 2333666968 M2P_SysMaxVolt_B1_08 "汇流排1单体最大电压  ";
CM_ SG_ 2333666969 M2P_Power_B1_09 "汇流排1实时功率";
CM_ SG_ 2333666969 M2P_SysremEngy_Chg_B1_09 "汇流排1充电剩余能量";
CM_ SG_ 2333666969 M2P_SysremEngy_DisChg_B1_09 "汇流排1放电剩余能量";
CM_ SG_ 2333666969 M2P_SysMaxVolt_B1_09 "汇流排1单体最大电压  ";
CM_ SG_ 2333666970 M2P_Power_B1_10 "汇流排1实时功率";
CM_ SG_ 2333666970 M2P_SysremEngy_Chg_B1_10 "汇流排1充电剩余能量";
CM_ SG_ 2333666970 M2P_SysremEngy_DisChg_B1_10 "汇流排1放电剩余能量";
CM_ SG_ 2333666970 M2P_SysMaxVolt_B1_10 "汇流排1单体最大电压  ";
CM_ SG_ 2333666971 M2P_Power_B1_11 "汇流排1实时功率";
CM_ SG_ 2333666971 M2P_SysremEngy_Chg_B1_11 "汇流排1充电剩余能量";
CM_ SG_ 2333666971 M2P_SysremEngy_DisChg_B1_11 "汇流排1放电剩余能量";
CM_ SG_ 2333666971 M2P_SysMaxVolt_B1_11 "汇流排1单体最大电压  ";
CM_ SG_ 2333666972 M2P_Power_B1_12 "汇流排1实时功率";
CM_ SG_ 2333666972 M2P_SysremEngy_Chg_B1_12 "汇流排1充电剩余能量";
CM_ SG_ 2333666972 M2P_SysremEngy_DisChg_B1_12 "汇流排1放电剩余能量";
CM_ SG_ 2333666972 M2P_SysMaxVolt_B1_12 "汇流排1单体最大电压  ";
CM_ SG_ 2333666973 M2P_Power_B1_13 "汇流排1实时功率";
CM_ SG_ 2333666973 M2P_SysremEngy_Chg_B1_13 "汇流排1充电剩余能量";
CM_ SG_ 2333666973 M2P_SysremEngy_DisChg_B1_13 "汇流排1放电剩余能量";
CM_ SG_ 2333666973 M2P_SysMaxVolt_B1_13 "汇流排1单体最大电压  ";
CM_ SG_ 2333666974 M2P_Power_B1_14 "汇流排1实时功率";
CM_ SG_ 2333666974 M2P_SysremEngy_Chg_B1_14 "汇流排1充电剩余能量";
CM_ SG_ 2333666974 M2P_SysremEngy_DisChg_B1_14 "汇流排1放电剩余能量";
CM_ SG_ 2333666974 M2P_SysMaxVolt_B1_14 "汇流排1单体最大电压  ";
CM_ SG_ 2333666975 M2P_Power_B1_15 "汇流排1实时功率";
CM_ SG_ 2333666975 M2P_SysremEngy_Chg_B1_15 "汇流排1充电剩余能量";
CM_ SG_ 2333666975 M2P_SysremEngy_DisChg_B1_15 "汇流排1放电剩余能量";
CM_ SG_ 2333666975 M2P_SysMaxVolt_B1_15 "汇流排1单体最大电压  ";
CM_ SG_ 2333666976 M2P_Power_B1_16 "汇流排1实时功率";
CM_ SG_ 2333666976 M2P_SysremEngy_Chg_B1_16 "汇流排1充电剩余能量";
CM_ SG_ 2333666976 M2P_SysremEngy_DisChg_B1_16 "汇流排1放电剩余能量";
CM_ SG_ 2333666976 M2P_SysMaxVolt_B1_16 "汇流排1单体最大电压  ";
CM_ SG_ 2333666977 M2P_Power_B1_17 "汇流排1实时功率";
CM_ SG_ 2333666977 M2P_SysremEngy_Chg_B1_17 "汇流排1充电剩余能量";
CM_ SG_ 2333666977 M2P_SysremEngy_DisChg_B1_17 "汇流排1放电剩余能量";
CM_ SG_ 2333666977 M2P_SysMaxVolt_B1_17 "汇流排1单体最大电压  ";
CM_ SG_ 2333666978 M2P_Power_B1_18 "汇流排1实时功率";
CM_ SG_ 2333666978 M2P_SysremEngy_Chg_B1_18 "汇流排1充电剩余能量";
CM_ SG_ 2333666978 M2P_SysremEngy_DisChg_B1_18 "汇流排1放电剩余能量";
CM_ SG_ 2333666978 M2P_SysMaxVolt_B1_18 "汇流排1单体最大电压  ";
CM_ SG_ 2333666979 M2P_Power_B1_19 "汇流排1实时功率";
CM_ SG_ 2333666979 M2P_SysremEngy_Chg_B1_19 "汇流排1充电剩余能量";
CM_ SG_ 2333666979 M2P_SysremEngy_DisChg_B1_19 "汇流排1放电剩余能量";
CM_ SG_ 2333666979 M2P_SysMaxVolt_B1_19 "汇流排1单体最大电压  ";
CM_ SG_ 2333666980 M2P_Power_B1_20 "汇流排1实时功率";
CM_ SG_ 2333666980 M2P_SysremEngy_Chg_B1_20 "汇流排1充电剩余能量";
CM_ SG_ 2333666980 M2P_SysremEngy_DisChg_B1_20 "汇流排1放电剩余能量";
CM_ SG_ 2333666980 M2P_SysMaxVolt_B1_20 "汇流排1单体最大电压  ";
CM_ SG_ 2333666981 M2P_Power_B1_21 "汇流排1实时功率";
CM_ SG_ 2333666981 M2P_SysremEngy_Chg_B1_21 "汇流排1充电剩余能量";
CM_ SG_ 2333666981 M2P_SysremEngy_DisChg_B1_21 "汇流排1放电剩余能量";
CM_ SG_ 2333666981 M2P_SysMaxVolt_B1_21 "汇流排1单体最大电压  ";
CM_ SG_ 2333666982 M2P_Power_B1_22 "汇流排1实时功率";
CM_ SG_ 2333666982 M2P_SysremEngy_Chg_B1_22 "汇流排1充电剩余能量";
CM_ SG_ 2333666982 M2P_SysremEngy_DisChg_B1_22 "汇流排1放电剩余能量";
CM_ SG_ 2333666982 M2P_SysMaxVolt_B1_22 "汇流排1单体最大电压  ";
CM_ SG_ 2333666983 M2P_Power_B1_23 "汇流排1实时功率";
CM_ SG_ 2333666983 M2P_SysremEngy_Chg_B1_23 "汇流排1充电剩余能量";
CM_ SG_ 2333666983 M2P_SysremEngy_DisChg_B1_23 "汇流排1放电剩余能量";
CM_ SG_ 2333666983 M2P_SysMaxVolt_B1_23 "汇流排1单体最大电压  ";
CM_ SG_ 2333666984 M2P_Power_B1_24 "汇流排1实时功率";
CM_ SG_ 2333666984 M2P_SysremEngy_Chg_B1_24 "汇流排1充电剩余能量";
CM_ SG_ 2333666984 M2P_SysremEngy_DisChg_B1_24 "汇流排1放电剩余能量";
CM_ SG_ 2333666984 M2P_SysMaxVolt_B1_24 "汇流排1单体最大电压  ";
CM_ SG_ 2333666985 M2P_Power_B1_25 "汇流排1实时功率";
CM_ SG_ 2333666985 M2P_SysremEngy_Chg_B1_25 "汇流排1充电剩余能量";
CM_ SG_ 2333666985 M2P_SysremEngy_DisChg_B1_25 "汇流排1放电剩余能量";
CM_ SG_ 2333666985 M2P_SysMaxVolt_B1_25 "汇流排1单体最大电压  ";
CM_ SG_ 2333666986 M2P_Power_B1_26 "汇流排1实时功率";
CM_ SG_ 2333666986 M2P_SysremEngy_Chg_B1_26 "汇流排1充电剩余能量";
CM_ SG_ 2333666986 M2P_SysremEngy_DisChg_B1_26 "汇流排1放电剩余能量";
CM_ SG_ 2333666986 M2P_SysMaxVolt_B1_26 "汇流排1单体最大电压  ";
CM_ SG_ 2333666987 M2P_Power_B1_27 "汇流排1实时功率";
CM_ SG_ 2333666987 M2P_SysremEngy_Chg_B1_27 "汇流排1充电剩余能量";
CM_ SG_ 2333666987 M2P_SysremEngy_DisChg_B1_27 "汇流排1放电剩余能量";
CM_ SG_ 2333666987 M2P_SysMaxVolt_B1_27 "汇流排1单体最大电压  ";
CM_ SG_ 2333666988 M2P_Power_B1_28 "汇流排1实时功率";
CM_ SG_ 2333666988 M2P_SysremEngy_Chg_B1_28 "汇流排1充电剩余能量";
CM_ SG_ 2333666988 M2P_SysremEngy_DisChg_B1_28 "汇流排1放电剩余能量";
CM_ SG_ 2333666988 M2P_SysMaxVolt_B1_28 "汇流排1单体最大电压  ";
CM_ SG_ 2333666989 M2P_Power_B1_29 "汇流排1实时功率";
CM_ SG_ 2333666989 M2P_SysremEngy_Chg_B1_29 "汇流排1充电剩余能量";
CM_ SG_ 2333666989 M2P_SysremEngy_DisChg_B1_29 "汇流排1放电剩余能量";
CM_ SG_ 2333666989 M2P_SysMaxVolt_B1_29 "汇流排1单体最大电压  ";
CM_ SG_ 2333666990 M2P_Power_B1_30 "汇流排1实时功率";
CM_ SG_ 2333666990 M2P_SysremEngy_Chg_B1_30 "汇流排1充电剩余能量";
CM_ SG_ 2333666990 M2P_SysremEngy_DisChg_B1_30 "汇流排1放电剩余能量";
CM_ SG_ 2333666990 M2P_SysMaxVolt_B1_30 "汇流排1单体最大电压  ";
CM_ SG_ 2333666991 M2P_Power_B1_31 "汇流排1实时功率";
CM_ SG_ 2333666991 M2P_SysremEngy_Chg_B1_31 "汇流排1充电剩余能量";
CM_ SG_ 2333666991 M2P_SysremEngy_DisChg_B1_31 "汇流排1放电剩余能量";
CM_ SG_ 2333666991 M2P_SysMaxVolt_B1_31 "汇流排1单体最大电压  ";
CM_ SG_ 2333732497 M2P_SysMinVolt_B1_01 "汇流排1单体最小电压";
CM_ SG_ 2333732497 M2P_SysAvgVolt_B1_01 "汇流排1单体平均电压";
CM_ SG_ 2333732497 M2P_BMS_Status_B1 "汇流排1能量状态";
CM_ SG_ 2333732497 M2P_SOC_B1 "汇流排1系统SOC";
CM_ SG_ 2333732497 M2P_SOH_B1 "汇流排1系统SOH";
CM_ SG_ 2333732497 Reserved_01 "预留";
CM_ SG_ 2333732498 M2P_SysMinVolt_B1_02 "汇流排1单体最小电压";
CM_ SG_ 2333732498 M2P_SysAvgVolt_B1_02 "汇流排1单体平均电压";
CM_ SG_ 2333732498 M2P_BMS_Status_B1 "汇流排1能量状态";
CM_ SG_ 2333732498 M2P_SOC_B1 "汇流排1系统SOC";
CM_ SG_ 2333732498 M2P_SOH_B1 "汇流排1系统SOH";
CM_ SG_ 2333732498 Reserved_02 "预留";
CM_ SG_ 2333732499 M2P_SysMinVolt_B1_03 "汇流排1单体最小电压";
CM_ SG_ 2333732499 M2P_SysAvgVolt_B1_03 "汇流排1单体平均电压";
CM_ SG_ 2333732499 M2P_BMS_Status_B1 "汇流排1能量状态";
CM_ SG_ 2333732499 M2P_SOC_B1 "汇流排1系统SOC";
CM_ SG_ 2333732499 M2P_SOH_B1 "汇流排1系统SOH";
CM_ SG_ 2333732499 Reserved_03 "预留";
CM_ SG_ 2333732500 M2P_SysMinVolt_B1_04 "汇流排1单体最小电压";
CM_ SG_ 2333732500 M2P_SysAvgVolt_B1_04 "汇流排1单体平均电压";
CM_ SG_ 2333732500 M2P_BMS_Status_B1 "汇流排1能量状态";
CM_ SG_ 2333732500 M2P_SOC_B1 "汇流排1系统SOC";
CM_ SG_ 2333732500 M2P_SOH_B1 "汇流排1系统SOH";
CM_ SG_ 2333732500 Reserved_04 "预留";
CM_ SG_ 2333732501 M2P_SysMinVolt_B1_05 "汇流排1单体最小电压";
CM_ SG_ 2333732501 M2P_SysAvgVolt_B1_05 "汇流排1单体平均电压";
CM_ SG_ 2333732501 M2P_BMS_Status_B1 "汇流排1能量状态";
CM_ SG_ 2333732501 M2P_SOC_B1 "汇流排1系统SOC";
CM_ SG_ 2333732501 M2P_SOH_B1 "汇流排1系统SOH";
CM_ SG_ 2333732501 Reserved_05 "预留";
CM_ SG_ 2333732502 M2P_SysMinVolt_B1_06 "汇流排1单体最小电压";
CM_ SG_ 2333732502 M2P_SysAvgVolt_B1_06 "汇流排1单体平均电压";
CM_ SG_ 2333732502 M2P_BMS_Status_B1 "汇流排1能量状态";
CM_ SG_ 2333732502 M2P_SOC_B1 "汇流排1系统SOC";
CM_ SG_ 2333732502 M2P_SOH_B1 "汇流排1系统SOH";
CM_ SG_ 2333732502 Reserved_06 "预留";
CM_ SG_ 2333732503 M2P_SysMinVolt_B1_07 "汇流排1单体最小电压";
CM_ SG_ 2333732503 M2P_SysAvgVolt_B1_07 "汇流排1单体平均电压";
CM_ SG_ 2333732503 M2P_BMS_Status_B1 "汇流排1能量状态";
CM_ SG_ 2333732503 M2P_SOC_B1 "汇流排1系统SOC";
CM_ SG_ 2333732503 M2P_SOH_B1 "汇流排1系统SOH";
CM_ SG_ 2333732503 Reserved_07 "预留";
CM_ SG_ 2333732504 M2P_SysMinVolt_B1_08 "汇流排1单体最小电压";
CM_ SG_ 2333732504 M2P_SysAvgVolt_B1_08 "汇流排1单体平均电压";
CM_ SG_ 2333732504 M2P_BMS_Status_B1 "汇流排1能量状态";
CM_ SG_ 2333732504 M2P_SOC_B1 "汇流排1系统SOC";
CM_ SG_ 2333732504 M2P_SOH_B1 "汇流排1系统SOH";
CM_ SG_ 2333732504 Reserved_08 "预留";
CM_ SG_ 2333732505 M2P_SysMinVolt_B1_09 "汇流排1单体最小电压";
CM_ SG_ 2333732505 M2P_SysAvgVolt_B1_09 "汇流排1单体平均电压";
CM_ SG_ 2333732505 M2P_BMS_Status_B1 "汇流排1能量状态";
CM_ SG_ 2333732505 M2P_SOC_B1 "汇流排1系统SOC";
CM_ SG_ 2333732505 M2P_SOH_B1 "汇流排1系统SOH";
CM_ SG_ 2333732505 Reserved_09 "预留";
CM_ SG_ 2333732506 M2P_SysMinVolt_B1_10 "汇流排1单体最小电压";
CM_ SG_ 2333732506 M2P_SysAvgVolt_B1_10 "汇流排1单体平均电压";
CM_ SG_ 2333732506 M2P_BMS_Status_B1 "汇流排1能量状态";
CM_ SG_ 2333732506 M2P_SOC_B1 "汇流排1系统SOC";
CM_ SG_ 2333732506 M2P_SOH_B1 "汇流排1系统SOH";
CM_ SG_ 2333732506 Reserved_10 "预留";
CM_ SG_ 2333732507 M2P_SysMinVolt_B1_11 "汇流排1单体最小电压";
CM_ SG_ 2333732507 M2P_SysAvgVolt_B1_11 "汇流排1单体平均电压";
CM_ SG_ 2333732507 M2P_BMS_Status_B1 "汇流排1能量状态";
CM_ SG_ 2333732507 M2P_SOC_B1 "汇流排1系统SOC";
CM_ SG_ 2333732507 M2P_SOH_B1 "汇流排1系统SOH";
CM_ SG_ 2333732507 Reserved_11 "预留";
CM_ SG_ 2333732508 M2P_SysMinVolt_B1_12 "汇流排1单体最小电压";
CM_ SG_ 2333732508 M2P_SysAvgVolt_B1_12 "汇流排1单体平均电压";
CM_ SG_ 2333732508 M2P_BMS_Status_B1 "汇流排1能量状态";
CM_ SG_ 2333732508 M2P_SOC_B1 "汇流排1系统SOC";
CM_ SG_ 2333732508 M2P_SOH_B1 "汇流排1系统SOH";
CM_ SG_ 2333732508 Reserved_12 "预留";
CM_ SG_ 2333732509 M2P_SysMinVolt_B1_13 "汇流排1单体最小电压";
CM_ SG_ 2333732509 M2P_SysAvgVolt_B1_13 "汇流排1单体平均电压";
CM_ SG_ 2333732509 M2P_BMS_Status_B1 "汇流排1能量状态";
CM_ SG_ 2333732509 M2P_SOC_B1 "汇流排1系统SOC";
CM_ SG_ 2333732509 M2P_SOH_B1 "汇流排1系统SOH";
CM_ SG_ 2333732509 Reserved_13 "预留";
CM_ SG_ 2333732510 M2P_SysMinVolt_B1_14 "汇流排1单体最小电压";
CM_ SG_ 2333732510 M2P_SysAvgVolt_B1_14 "汇流排1单体平均电压";
CM_ SG_ 2333732510 M2P_BMS_Status_B1 "汇流排1能量状态";
CM_ SG_ 2333732510 M2P_SOC_B1 "汇流排1系统SOC";
CM_ SG_ 2333732510 M2P_SOH_B1 "汇流排1系统SOH";
CM_ SG_ 2333732510 Reserved_14 "预留";
CM_ SG_ 2333732511 M2P_SysMinVolt_B1_15 "汇流排1单体最小电压";
CM_ SG_ 2333732511 M2P_SysAvgVolt_B1_15 "汇流排1单体平均电压";
CM_ SG_ 2333732511 M2P_BMS_Status_B1 "汇流排1能量状态";
CM_ SG_ 2333732511 M2P_SOC_B1 "汇流排1系统SOC";
CM_ SG_ 2333732511 M2P_SOH_B1 "汇流排1系统SOH";
CM_ SG_ 2333732511 Reserved_15 "预留";
CM_ SG_ 2333732512 M2P_SysMinVolt_B1_16 "汇流排1单体最小电压";
CM_ SG_ 2333732512 M2P_SysAvgVolt_B1_16 "汇流排1单体平均电压";
CM_ SG_ 2333732512 M2P_BMS_Status_B1 "汇流排1能量状态";
CM_ SG_ 2333732512 M2P_SOC_B1 "汇流排1系统SOC";
CM_ SG_ 2333732512 M2P_SOH_B1 "汇流排1系统SOH";
CM_ SG_ 2333732512 Reserved_16 "预留";
CM_ SG_ 2333732513 M2P_SysMinVolt_B1_17 "汇流排1单体最小电压";
CM_ SG_ 2333732513 M2P_SysAvgVolt_B1_17 "汇流排1单体平均电压";
CM_ SG_ 2333732513 M2P_BMS_Status_B1 "汇流排1能量状态";
CM_ SG_ 2333732513 M2P_SOC_B1 "汇流排1系统SOC";
CM_ SG_ 2333732513 M2P_SOH_B1 "汇流排1系统SOH";
CM_ SG_ 2333732513 Reserved_17 "预留";
CM_ SG_ 2333732514 M2P_SysMinVolt_B1_18 "汇流排1单体最小电压";
CM_ SG_ 2333732514 M2P_SysAvgVolt_B1_18 "汇流排1单体平均电压";
CM_ SG_ 2333732514 M2P_BMS_Status_B1 "汇流排1能量状态";
CM_ SG_ 2333732514 M2P_SOC_B1 "汇流排1系统SOC";
CM_ SG_ 2333732514 M2P_SOH_B1 "汇流排1系统SOH";
CM_ SG_ 2333732514 Reserved_18 "预留";
CM_ SG_ 2333732515 M2P_SysMinVolt_B1_19 "汇流排1单体最小电压";
CM_ SG_ 2333732515 M2P_SysAvgVolt_B1_19 "汇流排1单体平均电压";
CM_ SG_ 2333732515 M2P_BMS_Status_B1 "汇流排1能量状态";
CM_ SG_ 2333732515 M2P_SOC_B1 "汇流排1系统SOC";
CM_ SG_ 2333732515 M2P_SOH_B1 "汇流排1系统SOH";
CM_ SG_ 2333732515 Reserved_19 "预留";
CM_ SG_ 2333732516 M2P_SysMinVolt_B1_20 "汇流排1单体最小电压";
CM_ SG_ 2333732516 M2P_SysAvgVolt_B1_20 "汇流排1单体平均电压";
CM_ SG_ 2333732516 M2P_BMS_Status_B1 "汇流排1能量状态";
CM_ SG_ 2333732516 M2P_SOC_B1 "汇流排1系统SOC";
CM_ SG_ 2333732516 M2P_SOH_B1 "汇流排1系统SOH";
CM_ SG_ 2333732516 Reserved_20 "预留";
CM_ SG_ 2333732517 M2P_SysMinVolt_B1_21 "汇流排1单体最小电压";
CM_ SG_ 2333732517 M2P_SysAvgVolt_B1_21 "汇流排1单体平均电压";
CM_ SG_ 2333732517 M2P_BMS_Status_B1 "汇流排1能量状态";
CM_ SG_ 2333732517 M2P_SOC_B1 "汇流排1系统SOC";
CM_ SG_ 2333732517 M2P_SOH_B1 "汇流排1系统SOH";
CM_ SG_ 2333732517 Reserved_21 "预留";
CM_ SG_ 2333732518 M2P_SysMinVolt_B1_22 "汇流排1单体最小电压";
CM_ SG_ 2333732518 M2P_SysAvgVolt_B1_22 "汇流排1单体平均电压";
CM_ SG_ 2333732518 M2P_BMS_Status_B1 "汇流排1能量状态";
CM_ SG_ 2333732518 M2P_SOC_B1 "汇流排1系统SOC";
CM_ SG_ 2333732518 M2P_SOH_B1 "汇流排1系统SOH";
CM_ SG_ 2333732518 Reserved_22 "预留";
CM_ SG_ 2333732519 M2P_SysMinVolt_B1_23 "汇流排1单体最小电压";
CM_ SG_ 2333732519 M2P_SysAvgVolt_B1_23 "汇流排1单体平均电压";
CM_ SG_ 2333732519 M2P_BMS_Status_B1 "汇流排1能量状态";
CM_ SG_ 2333732519 M2P_SOC_B1 "汇流排1系统SOC";
CM_ SG_ 2333732519 M2P_SOH_B1 "汇流排1系统SOH";
CM_ SG_ 2333732519 Reserved_23 "预留";
CM_ SG_ 2333732520 M2P_SysMinVolt_B1_24 "汇流排1单体最小电压";
CM_ SG_ 2333732520 M2P_SysAvgVolt_B1_24 "汇流排1单体平均电压";
CM_ SG_ 2333732520 M2P_BMS_Status_B1 "汇流排1能量状态";
CM_ SG_ 2333732520 M2P_SOC_B1 "汇流排1系统SOC";
CM_ SG_ 2333732520 M2P_SOH_B1 "汇流排1系统SOH";
CM_ SG_ 2333732520 Reserved_24 "预留";
CM_ SG_ 2333732521 M2P_SysMinVolt_B1_25 "汇流排1单体最小电压";
CM_ SG_ 2333732521 M2P_SysAvgVolt_B1_25 "汇流排1单体平均电压";
CM_ SG_ 2333732521 M2P_BMS_Status_B1 "汇流排1能量状态";
CM_ SG_ 2333732521 M2P_SOC_B1 "汇流排1系统SOC";
CM_ SG_ 2333732521 M2P_SOH_B1 "汇流排1系统SOH";
CM_ SG_ 2333732521 Reserved_25 "预留";
CM_ SG_ 2333732522 M2P_SysMinVolt_B1_26 "汇流排1单体最小电压";
CM_ SG_ 2333732522 M2P_SysAvgVolt_B1_26 "汇流排1单体平均电压";
CM_ SG_ 2333732522 M2P_BMS_Status_B1 "汇流排1能量状态";
CM_ SG_ 2333732522 M2P_SOC_B1 "汇流排1系统SOC";
CM_ SG_ 2333732522 M2P_SOH_B1 "汇流排1系统SOH";
CM_ SG_ 2333732522 Reserved_26 "预留";
CM_ SG_ 2333732523 M2P_SysMinVolt_B1_27 "汇流排1单体最小电压";
CM_ SG_ 2333732523 M2P_SysAvgVolt_B1_27 "汇流排1单体平均电压";
CM_ SG_ 2333732523 M2P_BMS_Status_B1 "汇流排1能量状态";
CM_ SG_ 2333732523 M2P_SOC_B1 "汇流排1系统SOC";
CM_ SG_ 2333732523 M2P_SOH_B1 "汇流排1系统SOH";
CM_ SG_ 2333732523 Reserved_27 "预留";
CM_ SG_ 2333732524 M2P_SysMinVolt_B1_28 "汇流排1单体最小电压";
CM_ SG_ 2333732524 M2P_SysAvgVolt_B1_28 "汇流排1单体平均电压";
CM_ SG_ 2333732524 M2P_BMS_Status_B1 "汇流排1能量状态";
CM_ SG_ 2333732524 M2P_SOC_B1 "汇流排1系统SOC";
CM_ SG_ 2333732524 M2P_SOH_B1 "汇流排1系统SOH";
CM_ SG_ 2333732524 Reserved_28 "预留";
CM_ SG_ 2333732525 M2P_SysMinVolt_B1_29 "汇流排1单体最小电压";
CM_ SG_ 2333732525 M2P_SysAvgVolt_B1_29 "汇流排1单体平均电压";
CM_ SG_ 2333732525 M2P_BMS_Status_B1 "汇流排1能量状态";
CM_ SG_ 2333732525 M2P_SOC_B1 "汇流排1系统SOC";
CM_ SG_ 2333732525 M2P_SOH_B1 "汇流排1系统SOH";
CM_ SG_ 2333732525 Reserved_29 "预留";
CM_ SG_ 2333732526 M2P_SysMinVolt_B1_30 "汇流排1单体最小电压";
CM_ SG_ 2333732526 M2P_SysAvgVolt_B1_30 "汇流排1单体平均电压";
CM_ SG_ 2333732526 M2P_BMS_Status_B1 "汇流排1能量状态";
CM_ SG_ 2333732526 M2P_SOC_B1 "汇流排1系统SOC";
CM_ SG_ 2333732526 M2P_SOH_B1 "汇流排1系统SOH";
CM_ SG_ 2333732526 Reserved_30 "预留";
CM_ SG_ 2333732527 M2P_SysMinVolt_B1_31 "汇流排1单体最小电压";
CM_ SG_ 2333732527 M2P_SysAvgVolt_B1_31 "汇流排1单体平均电压";
CM_ SG_ 2333732527 M2P_BMS_Status_B1 "汇流排1能量状态";
CM_ SG_ 2333732527 M2P_SOC_B1 "汇流排1系统SOC";
CM_ SG_ 2333732527 M2P_SOH_B1 "汇流排1系统SOH";
CM_ SG_ 2333732527 Reserved_31 "预留";
CM_ SG_ 2333798033 M2P_SOE_Charge_B1 "汇流排1系可充电SOE";
CM_ SG_ 2333798033 M2P_SOE_Discharge_B1 "汇流排1系可放电SOE";
CM_ SG_ 2333798033 Reserved_01 "预留";
CM_ SG_ 2333798034 M2P_SOE_Charge_B1 "汇流排1系可充电SOE";
CM_ SG_ 2333798034 M2P_SOE_Discharge_B1 "汇流排1系可放电SOE";
CM_ SG_ 2333798034 Reserved_02 "预留";
CM_ SG_ 2333798035 M2P_SOE_Charge_B1 "汇流排1系可充电SOE";
CM_ SG_ 2333798035 M2P_SOE_Discharge_B1 "汇流排1系可放电SOE";
CM_ SG_ 2333798035 Reserved_03 "预留";
CM_ SG_ 2333798036 M2P_SOE_Charge_B1 "汇流排1系可充电SOE";
CM_ SG_ 2333798036 M2P_SOE_Discharge_B1 "汇流排1系可放电SOE";
CM_ SG_ 2333798036 Reserved_04 "预留";
CM_ SG_ 2333798037 M2P_SOE_Charge_B1 "汇流排1系可充电SOE";
CM_ SG_ 2333798037 M2P_SOE_Discharge_B1 "汇流排1系可放电SOE";
CM_ SG_ 2333798037 Reserved_05 "预留";
CM_ SG_ 2333798038 M2P_SOE_Charge_B1 "汇流排1系可充电SOE";
CM_ SG_ 2333798038 M2P_SOE_Discharge_B1 "汇流排1系可放电SOE";
CM_ SG_ 2333798038 Reserved_06 "预留";
CM_ SG_ 2333798039 M2P_SOE_Charge_B1 "汇流排1系可充电SOE";
CM_ SG_ 2333798039 M2P_SOE_Discharge_B1 "汇流排1系可放电SOE";
CM_ SG_ 2333798039 Reserved_07 "预留";
CM_ SG_ 2333798040 M2P_SOE_Charge_B1 "汇流排1系可充电SOE";
CM_ SG_ 2333798040 M2P_SOE_Discharge_B1 "汇流排1系可放电SOE";
CM_ SG_ 2333798040 Reserved_08 "预留";
CM_ SG_ 2333798041 M2P_SOE_Charge_B1 "汇流排1系可充电SOE";
CM_ SG_ 2333798041 M2P_SOE_Discharge_B1 "汇流排1系可放电SOE";
CM_ SG_ 2333798041 Reserved_09 "预留";
CM_ SG_ 2333798042 M2P_SOE_Charge_B1 "汇流排1系可充电SOE";
CM_ SG_ 2333798042 M2P_SOE_Discharge_B1 "汇流排1系可放电SOE";
CM_ SG_ 2333798042 Reserved_10 "预留";
CM_ SG_ 2333798043 M2P_SOE_Charge_B1 "汇流排1系可充电SOE";
CM_ SG_ 2333798043 M2P_SOE_Discharge_B1 "汇流排1系可放电SOE";
CM_ SG_ 2333798043 Reserved_11 "预留";
CM_ SG_ 2333798044 M2P_SOE_Charge_B1 "汇流排1系可充电SOE";
CM_ SG_ 2333798044 M2P_SOE_Discharge_B1 "汇流排1系可放电SOE";
CM_ SG_ 2333798044 Reserved_12 "预留";
CM_ SG_ 2333798045 M2P_SOE_Charge_B1 "汇流排1系可充电SOE";
CM_ SG_ 2333798045 M2P_SOE_Discharge_B1 "汇流排1系可放电SOE";
CM_ SG_ 2333798045 Reserved_13 "预留";
CM_ SG_ 2333798046 M2P_SOE_Charge_B1 "汇流排1系可充电SOE";
CM_ SG_ 2333798046 M2P_SOE_Discharge_B1 "汇流排1系可放电SOE";
CM_ SG_ 2333798046 Reserved_14 "预留";
CM_ SG_ 2333798047 M2P_SOE_Charge_B1 "汇流排1系可充电SOE";
CM_ SG_ 2333798047 M2P_SOE_Discharge_B1 "汇流排1系可放电SOE";
CM_ SG_ 2333798047 Reserved_15 "预留";
CM_ SG_ 2333798048 M2P_SOE_Charge_B1 "汇流排1系可充电SOE";
CM_ SG_ 2333798048 M2P_SOE_Discharge_B1 "汇流排1系可放电SOE";
CM_ SG_ 2333798048 Reserved_16 "预留";
CM_ SG_ 2333798049 M2P_SOE_Charge_B1 "汇流排1系可充电SOE";
CM_ SG_ 2333798049 M2P_SOE_Discharge_B1 "汇流排1系可放电SOE";
CM_ SG_ 2333798049 Reserved_17 "预留";
CM_ SG_ 2333798050 M2P_SOE_Charge_B1 "汇流排1系可充电SOE";
CM_ SG_ 2333798050 M2P_SOE_Discharge_B1 "汇流排1系可放电SOE";
CM_ SG_ 2333798050 Reserved_18 "预留";
CM_ SG_ 2333798051 M2P_SOE_Charge_B1 "汇流排1系可充电SOE";
CM_ SG_ 2333798051 M2P_SOE_Discharge_B1 "汇流排1系可放电SOE";
CM_ SG_ 2333798051 Reserved_19 "预留";
CM_ SG_ 2333798052 M2P_SOE_Charge_B1 "汇流排1系可充电SOE";
CM_ SG_ 2333798052 M2P_SOE_Discharge_B1 "汇流排1系可放电SOE";
CM_ SG_ 2333798052 Reserved_20 "预留";
CM_ SG_ 2333798053 M2P_SOE_Charge_B1 "汇流排1系可充电SOE";
CM_ SG_ 2333798053 M2P_SOE_Discharge_B1 "汇流排1系可放电SOE";
CM_ SG_ 2333798053 Reserved_21 "预留";
CM_ SG_ 2333798054 M2P_SOE_Charge_B1 "汇流排1系可充电SOE";
CM_ SG_ 2333798054 M2P_SOE_Discharge_B1 "汇流排1系可放电SOE";
CM_ SG_ 2333798054 Reserved_22 "预留";
CM_ SG_ 2333798055 M2P_SOE_Charge_B1 "汇流排1系可充电SOE";
CM_ SG_ 2333798055 M2P_SOE_Discharge_B1 "汇流排1系可放电SOE";
CM_ SG_ 2333798055 Reserved_23 "预留";
CM_ SG_ 2333798056 M2P_SOE_Charge_B1 "汇流排1系可充电SOE";
CM_ SG_ 2333798056 M2P_SOE_Discharge_B1 "汇流排1系可放电SOE";
CM_ SG_ 2333798056 Reserved_24 "预留";
CM_ SG_ 2333798057 M2P_SOE_Charge_B1 "汇流排1系可充电SOE";
CM_ SG_ 2333798057 M2P_SOE_Discharge_B1 "汇流排1系可放电SOE";
CM_ SG_ 2333798057 Reserved_25 "预留";
CM_ SG_ 2333798058 M2P_SOE_Charge_B1 "汇流排1系可充电SOE";
CM_ SG_ 2333798058 M2P_SOE_Discharge_B1 "汇流排1系可放电SOE";
CM_ SG_ 2333798058 Reserved_26 "预留";
CM_ SG_ 2333798059 M2P_SOE_Charge_B1 "汇流排1系可充电SOE";
CM_ SG_ 2333798059 M2P_SOE_Discharge_B1 "汇流排1系可放电SOE";
CM_ SG_ 2333798059 Reserved_27 "预留";
CM_ SG_ 2333798060 M2P_SOE_Charge_B1 "汇流排1系可充电SOE";
CM_ SG_ 2333798060 M2P_SOE_Discharge_B1 "汇流排1系可放电SOE";
CM_ SG_ 2333798060 Reserved_28 "预留";
CM_ SG_ 2333798061 M2P_SOE_Charge_B1 "汇流排1系可充电SOE";
CM_ SG_ 2333798061 M2P_SOE_Discharge_B1 "汇流排1系可放电SOE";
CM_ SG_ 2333798061 Reserved_29 "预留";
CM_ SG_ 2333798062 M2P_SOE_Charge_B1 "汇流排1系可充电SOE";
CM_ SG_ 2333798062 M2P_SOE_Discharge_B1 "汇流排1系可放电SOE";
CM_ SG_ 2333798062 Reserved_30 "预留";
CM_ SG_ 2333798063 M2P_SOE_Charge_B1 "汇流排1系可充电SOE";
CM_ SG_ 2333798063 M2P_SOE_Discharge_B1 "汇流排1系可放电SOE";
CM_ SG_ 2333798063 Reserved_31 "预留";
CM_ SG_ 2333863569 M2P_Measure_Vol_B2_01 "汇流排2所有高压在线电柜外侧电压平均值    ";
CM_ SG_ 2333863569 M2P_Current_B2_01 "汇流排2所有电柜电流累加和";
CM_ SG_ 2333863569 M2P_PermitMaxCharge_I_B2_01 "汇流排2最大允许充电电流";
CM_ SG_ 2333863569 M2P_PermitMaxDisCharge_I_B2_01 "汇流排2最大允许放电电流";
CM_ SG_ 2333863570 M2P_Measure_Vol_B2_02 "汇流排2所有高压在线电柜外侧电压平均值    ";
CM_ SG_ 2333863570 M2P_Current_B2_02 "汇流排2所有电柜电流累加和";
CM_ SG_ 2333863570 M2P_PermitMaxCharge_I_B2_02 "汇流排2最大允许充电电流";
CM_ SG_ 2333863570 M2P_PermitMaxDisCharge_I_B2_02 "汇流排2最大允许放电电流";
CM_ SG_ 2333863571 M2P_Measure_Vol_B2_03 "汇流排2所有高压在线电柜外侧电压平均值    ";
CM_ SG_ 2333863571 M2P_Current_B2_03 "汇流排2所有电柜电流累加和";
CM_ SG_ 2333863571 M2P_PermitMaxCharge_I_B2_03 "汇流排2最大允许充电电流";
CM_ SG_ 2333863571 M2P_PermitMaxDisCharge_I_B2_03 "汇流排2最大允许放电电流";
CM_ SG_ 2333863572 M2P_Measure_Vol_B2_04 "汇流排2所有高压在线电柜外侧电压平均值    ";
CM_ SG_ 2333863572 M2P_Current_B2_04 "汇流排2所有电柜电流累加和";
CM_ SG_ 2333863572 M2P_PermitMaxCharge_I_B2_04 "汇流排2最大允许充电电流";
CM_ SG_ 2333863572 M2P_PermitMaxDisCharge_I_B2_04 "汇流排2最大允许放电电流";
CM_ SG_ 2333863573 M2P_Measure_Vol_B2_05 "汇流排2所有高压在线电柜外侧电压平均值    ";
CM_ SG_ 2333863573 M2P_Current_B2_05 "汇流排2所有电柜电流累加和";
CM_ SG_ 2333863573 M2P_PermitMaxCharge_I_B2_05 "汇流排2最大允许充电电流";
CM_ SG_ 2333863573 M2P_PermitMaxDisCharge_I_B2_05 "汇流排2最大允许放电电流";
CM_ SG_ 2333863574 M2P_Measure_Vol_B2_06 "汇流排2所有高压在线电柜外侧电压平均值    ";
CM_ SG_ 2333863574 M2P_Current_B2_06 "汇流排2所有电柜电流累加和";
CM_ SG_ 2333863574 M2P_PermitMaxCharge_I_B2_06 "汇流排2最大允许充电电流";
CM_ SG_ 2333863574 M2P_PermitMaxDisCharge_I_B2_06 "汇流排2最大允许放电电流";
CM_ SG_ 2333863575 M2P_Measure_Vol_B2_07 "汇流排2所有高压在线电柜外侧电压平均值    ";
CM_ SG_ 2333863575 M2P_Current_B2_07 "汇流排2所有电柜电流累加和";
CM_ SG_ 2333863575 M2P_PermitMaxCharge_I_B2_07 "汇流排2最大允许充电电流";
CM_ SG_ 2333863575 M2P_PermitMaxDisCharge_I_B2_07 "汇流排2最大允许放电电流";
CM_ SG_ 2333863576 M2P_Measure_Vol_B2_08 "汇流排2所有高压在线电柜外侧电压平均值    ";
CM_ SG_ 2333863576 M2P_Current_B2_08 "汇流排2所有电柜电流累加和";
CM_ SG_ 2333863576 M2P_PermitMaxCharge_I_B2_08 "汇流排2最大允许充电电流";
CM_ SG_ 2333863576 M2P_PermitMaxDisCharge_I_B2_08 "汇流排2最大允许放电电流";
CM_ SG_ 2333863577 M2P_Measure_Vol_B2_09 "汇流排2所有高压在线电柜外侧电压平均值    ";
CM_ SG_ 2333863577 M2P_Current_B2_09 "汇流排2所有电柜电流累加和";
CM_ SG_ 2333863577 M2P_PermitMaxCharge_I_B2_09 "汇流排2最大允许充电电流";
CM_ SG_ 2333863577 M2P_PermitMaxDisCharge_I_B2_09 "汇流排2最大允许放电电流";
CM_ SG_ 2333863578 M2P_Measure_Vol_B2_10 "汇流排2所有高压在线电柜外侧电压平均值    ";
CM_ SG_ 2333863578 M2P_Current_B2_10 "汇流排2所有电柜电流累加和";
CM_ SG_ 2333863578 M2P_PermitMaxCharge_I_B2_10 "汇流排2最大允许充电电流";
CM_ SG_ 2333863578 M2P_PermitMaxDisCharge_I_B2_10 "汇流排2最大允许放电电流";
CM_ SG_ 2333863579 M2P_Measure_Vol_B2_11 "汇流排2所有高压在线电柜外侧电压平均值    ";
CM_ SG_ 2333863579 M2P_Current_B2_11 "汇流排2所有电柜电流累加和";
CM_ SG_ 2333863579 M2P_PermitMaxCharge_I_B2_11 "汇流排2最大允许充电电流";
CM_ SG_ 2333863579 M2P_PermitMaxDisCharge_I_B2_11 "汇流排2最大允许放电电流";
CM_ SG_ 2333863580 M2P_Measure_Vol_B2_12 "汇流排2所有高压在线电柜外侧电压平均值    ";
CM_ SG_ 2333863580 M2P_Current_B2_12 "汇流排2所有电柜电流累加和";
CM_ SG_ 2333863580 M2P_PermitMaxCharge_I_B2_12 "汇流排2最大允许充电电流";
CM_ SG_ 2333863580 M2P_PermitMaxDisCharge_I_B2_12 "汇流排2最大允许放电电流";
CM_ SG_ 2333863581 M2P_Measure_Vol_B2_13 "汇流排2所有高压在线电柜外侧电压平均值    ";
CM_ SG_ 2333863581 M2P_Current_B2_13 "汇流排2所有电柜电流累加和";
CM_ SG_ 2333863581 M2P_PermitMaxCharge_I_B2_13 "汇流排2最大允许充电电流";
CM_ SG_ 2333863581 M2P_PermitMaxDisCharge_I_B2_13 "汇流排2最大允许放电电流";
CM_ SG_ 2333863582 M2P_Measure_Vol_B2_14 "汇流排2所有高压在线电柜外侧电压平均值    ";
CM_ SG_ 2333863582 M2P_Current_B2_14 "汇流排2所有电柜电流累加和";
CM_ SG_ 2333863582 M2P_PermitMaxCharge_I_B2_14 "汇流排2最大允许充电电流";
CM_ SG_ 2333863582 M2P_PermitMaxDisCharge_I_B2_14 "汇流排2最大允许放电电流";
CM_ SG_ 2333863583 M2P_Measure_Vol_B2_15 "汇流排2所有高压在线电柜外侧电压平均值    ";
CM_ SG_ 2333863583 M2P_Current_B2_15 "汇流排2所有电柜电流累加和";
CM_ SG_ 2333863583 M2P_PermitMaxCharge_I_B2_15 "汇流排2最大允许充电电流";
CM_ SG_ 2333863583 M2P_PermitMaxDisCharge_I_B2_15 "汇流排2最大允许放电电流";
CM_ SG_ 2333863584 M2P_Measure_Vol_B2_16 "汇流排2所有高压在线电柜外侧电压平均值    ";
CM_ SG_ 2333863584 M2P_Current_B2_16 "汇流排2所有电柜电流累加和";
CM_ SG_ 2333863584 M2P_PermitMaxCharge_I_B2_16 "汇流排2最大允许充电电流";
CM_ SG_ 2333863584 M2P_PermitMaxDisCharge_I_B2_16 "汇流排2最大允许放电电流";
CM_ SG_ 2333863585 M2P_Measure_Vol_B2_17 "汇流排2所有高压在线电柜外侧电压平均值    ";
CM_ SG_ 2333863585 M2P_Current_B2_17 "汇流排2所有电柜电流累加和";
CM_ SG_ 2333863585 M2P_PermitMaxCharge_I_B2_17 "汇流排2最大允许充电电流";
CM_ SG_ 2333863585 M2P_PermitMaxDisCharge_I_B2_17 "汇流排2最大允许放电电流";
CM_ SG_ 2333863586 M2P_Measure_Vol_B2_18 "汇流排2所有高压在线电柜外侧电压平均值    ";
CM_ SG_ 2333863586 M2P_Current_B2_18 "汇流排2所有电柜电流累加和";
CM_ SG_ 2333863586 M2P_PermitMaxCharge_I_B2_18 "汇流排2最大允许充电电流";
CM_ SG_ 2333863586 M2P_PermitMaxDisCharge_I_B2_18 "汇流排2最大允许放电电流";
CM_ SG_ 2333863587 M2P_Measure_Vol_B2_19 "汇流排2所有高压在线电柜外侧电压平均值    ";
CM_ SG_ 2333863587 M2P_Current_B2_19 "汇流排2所有电柜电流累加和";
CM_ SG_ 2333863587 M2P_PermitMaxCharge_I_B2_19 "汇流排2最大允许充电电流";
CM_ SG_ 2333863587 M2P_PermitMaxDisCharge_I_B2_19 "汇流排2最大允许放电电流";
CM_ SG_ 2333863588 M2P_Measure_Vol_B2_20 "汇流排2所有高压在线电柜外侧电压平均值    ";
CM_ SG_ 2333863588 M2P_Current_B2_20 "汇流排2所有电柜电流累加和";
CM_ SG_ 2333863588 M2P_PermitMaxCharge_I_B2_20 "汇流排2最大允许充电电流";
CM_ SG_ 2333863588 M2P_PermitMaxDisCharge_I_B2_20 "汇流排2最大允许放电电流";
CM_ SG_ 2333863589 M2P_Measure_Vol_B2_21 "汇流排2所有高压在线电柜外侧电压平均值    ";
CM_ SG_ 2333863589 M2P_Current_B2_21 "汇流排2所有电柜电流累加和";
CM_ SG_ 2333863589 M2P_PermitMaxCharge_I_B2_21 "汇流排2最大允许充电电流";
CM_ SG_ 2333863589 M2P_PermitMaxDisCharge_I_B2_21 "汇流排2最大允许放电电流";
CM_ SG_ 2333863590 M2P_Measure_Vol_B2_22 "汇流排2所有高压在线电柜外侧电压平均值    ";
CM_ SG_ 2333863590 M2P_Current_B2_22 "汇流排2所有电柜电流累加和";
CM_ SG_ 2333863590 M2P_PermitMaxCharge_I_B2_22 "汇流排2最大允许充电电流";
CM_ SG_ 2333863590 M2P_PermitMaxDisCharge_I_B2_22 "汇流排2最大允许放电电流";
CM_ SG_ 2333863591 M2P_Measure_Vol_B2_23 "汇流排2所有高压在线电柜外侧电压平均值    ";
CM_ SG_ 2333863591 M2P_Current_B2_23 "汇流排2所有电柜电流累加和";
CM_ SG_ 2333863591 M2P_PermitMaxCharge_I_B2_23 "汇流排2最大允许充电电流";
CM_ SG_ 2333863591 M2P_PermitMaxDisCharge_I_B2_23 "汇流排2最大允许放电电流";
CM_ SG_ 2333863592 M2P_Measure_Vol_B2_24 "汇流排2所有高压在线电柜外侧电压平均值    ";
CM_ SG_ 2333863592 M2P_Current_B2_24 "汇流排2所有电柜电流累加和";
CM_ SG_ 2333863592 M2P_PermitMaxCharge_I_B2_24 "汇流排2最大允许充电电流";
CM_ SG_ 2333863592 M2P_PermitMaxDisCharge_I_B2_24 "汇流排2最大允许放电电流";
CM_ SG_ 2333863593 M2P_Measure_Vol_B2_25 "汇流排2所有高压在线电柜外侧电压平均值    ";
CM_ SG_ 2333863593 M2P_Current_B2_25 "汇流排2所有电柜电流累加和";
CM_ SG_ 2333863593 M2P_PermitMaxCharge_I_B2_25 "汇流排2最大允许充电电流";
CM_ SG_ 2333863593 M2P_PermitMaxDisCharge_I_B2_25 "汇流排2最大允许放电电流";
CM_ SG_ 2333863594 M2P_Measure_Vol_B2_26 "汇流排2所有高压在线电柜外侧电压平均值    ";
CM_ SG_ 2333863594 M2P_Current_B2_26 "汇流排2所有电柜电流累加和";
CM_ SG_ 2333863594 M2P_PermitMaxCharge_I_B2_26 "汇流排2最大允许充电电流";
CM_ SG_ 2333863594 M2P_PermitMaxDisCharge_I_B2_26 "汇流排2最大允许放电电流";
CM_ SG_ 2333863595 M2P_Measure_Vol_B2_27 "汇流排2所有高压在线电柜外侧电压平均值    ";
CM_ SG_ 2333863595 M2P_Current_B2_27 "汇流排2所有电柜电流累加和";
CM_ SG_ 2333863595 M2P_PermitMaxCharge_I_B2_27 "汇流排2最大允许充电电流";
CM_ SG_ 2333863595 M2P_PermitMaxDisCharge_I_B2_27 "汇流排2最大允许放电电流";
CM_ SG_ 2333863596 M2P_Measure_Vol_B2_28 "汇流排2所有高压在线电柜外侧电压平均值    ";
CM_ SG_ 2333863596 M2P_Current_B2_28 "汇流排2所有电柜电流累加和";
CM_ SG_ 2333863596 M2P_PermitMaxCharge_I_B2_28 "汇流排2最大允许充电电流";
CM_ SG_ 2333863596 M2P_PermitMaxDisCharge_I_B2_28 "汇流排2最大允许放电电流";
CM_ SG_ 2333863597 M2P_Measure_Vol_B2_29 "汇流排2所有高压在线电柜外侧电压平均值    ";
CM_ SG_ 2333863597 M2P_Current_B2_29 "汇流排2所有电柜电流累加和";
CM_ SG_ 2333863597 M2P_PermitMaxCharge_I_B2_29 "汇流排2最大允许充电电流";
CM_ SG_ 2333863597 M2P_PermitMaxDisCharge_I_B2_29 "汇流排2最大允许放电电流";
CM_ SG_ 2333863598 M2P_Measure_Vol_B2_30 "汇流排2所有高压在线电柜外侧电压平均值    ";
CM_ SG_ 2333863598 M2P_Current_B2_30 "汇流排2所有电柜电流累加和";
CM_ SG_ 2333863598 M2P_PermitMaxCharge_I_B2_30 "汇流排2最大允许充电电流";
CM_ SG_ 2333863598 M2P_PermitMaxDisCharge_I_B2_30 "汇流排2最大允许放电电流";
CM_ SG_ 2333863599 M2P_Measure_Vol_B2_31 "汇流排2所有高压在线电柜外侧电压平均值    ";
CM_ SG_ 2333863599 M2P_Current_B2_31 "汇流排2所有电柜电流累加和";
CM_ SG_ 2333863599 M2P_PermitMaxCharge_I_B2_31 "汇流排2最大允许充电电流";
CM_ SG_ 2333863599 M2P_PermitMaxDisCharge_I_B2_31 "汇流排2最大允许放电电流";
CM_ SG_ 2333929105 M2P_PermitMaxVolt_B2_01 "汇流排2最高允许充电电压 （配置量）";
CM_ SG_ 2333929105 M2P_PermitMinVolt_B2_01 "汇流排2最低允许放电电压 （配置量）";
CM_ SG_ 2333929105 M2P_PermitMaxPow_Chg_B2_01 "汇流排2最大允许充电功率";
CM_ SG_ 2333929105 M2P_PermitMaxPow_DisChg_B2_01 "汇流排2最大允许放电功率";
CM_ SG_ 2333929106 M2P_PermitMaxVolt_B2_02 "汇流排2最高允许充电电压 （配置量）";
CM_ SG_ 2333929106 M2P_PermitMinVolt_B2_02 "汇流排2最低允许放电电压 （配置量）";
CM_ SG_ 2333929106 M2P_PermitMaxPow_Chg_B2_02 "汇流排2最大允许充电功率";
CM_ SG_ 2333929106 M2P_PermitMaxPow_DisChg_B2_02 "汇流排2最大允许放电功率";
CM_ SG_ 2333929107 M2P_PermitMaxVolt_B2_03 "汇流排2最高允许充电电压 （配置量）";
CM_ SG_ 2333929107 M2P_PermitMinVolt_B2_03 "汇流排2最低允许放电电压 （配置量）";
CM_ SG_ 2333929107 M2P_PermitMaxPow_Chg_B2_03 "汇流排2最大允许充电功率";
CM_ SG_ 2333929107 M2P_PermitMaxPow_DisChg_B2_03 "汇流排2最大允许放电功率";
CM_ SG_ 2333929108 M2P_PermitMaxVolt_B2_04 "汇流排2最高允许充电电压 （配置量）";
CM_ SG_ 2333929108 M2P_PermitMinVolt_B2_04 "汇流排2最低允许放电电压 （配置量）";
CM_ SG_ 2333929108 M2P_PermitMaxPow_Chg_B2_04 "汇流排2最大允许充电功率";
CM_ SG_ 2333929108 M2P_PermitMaxPow_DisChg_B2_04 "汇流排2最大允许放电功率";
CM_ SG_ 2333929109 M2P_PermitMaxVolt_B2_05 "汇流排2最高允许充电电压 （配置量）";
CM_ SG_ 2333929109 M2P_PermitMinVolt_B2_05 "汇流排2最低允许放电电压 （配置量）";
CM_ SG_ 2333929109 M2P_PermitMaxPow_Chg_B2_05 "汇流排2最大允许充电功率";
CM_ SG_ 2333929109 M2P_PermitMaxPow_DisChg_B2_05 "汇流排2最大允许放电功率";
CM_ SG_ 2333929110 M2P_PermitMaxVolt_B2_06 "汇流排2最高允许充电电压 （配置量）";
CM_ SG_ 2333929110 M2P_PermitMinVolt_B2_06 "汇流排2最低允许放电电压 （配置量）";
CM_ SG_ 2333929110 M2P_PermitMaxPow_Chg_B2_06 "汇流排2最大允许充电功率";
CM_ SG_ 2333929110 M2P_PermitMaxPow_DisChg_B2_06 "汇流排2最大允许放电功率";
CM_ SG_ 2333929111 M2P_PermitMaxVolt_B2_07 "汇流排2最高允许充电电压 （配置量）";
CM_ SG_ 2333929111 M2P_PermitMinVolt_B2_07 "汇流排2最低允许放电电压 （配置量）";
CM_ SG_ 2333929111 M2P_PermitMaxPow_Chg_B2_07 "汇流排2最大允许充电功率";
CM_ SG_ 2333929111 M2P_PermitMaxPow_DisChg_B2_07 "汇流排2最大允许放电功率";
CM_ SG_ 2333929112 M2P_PermitMaxVolt_B2_08 "汇流排2最高允许充电电压 （配置量）";
CM_ SG_ 2333929112 M2P_PermitMinVolt_B2_08 "汇流排2最低允许放电电压 （配置量）";
CM_ SG_ 2333929112 M2P_PermitMaxPow_Chg_B2_08 "汇流排2最大允许充电功率";
CM_ SG_ 2333929112 M2P_PermitMaxPow_DisChg_B2_08 "汇流排2最大允许放电功率";
CM_ SG_ 2333929113 M2P_PermitMaxVolt_B2_09 "汇流排2最高允许充电电压 （配置量）";
CM_ SG_ 2333929113 M2P_PermitMinVolt_B2_09 "汇流排2最低允许放电电压 （配置量）";
CM_ SG_ 2333929113 M2P_PermitMaxPow_Chg_B2_09 "汇流排2最大允许充电功率";
CM_ SG_ 2333929113 M2P_PermitMaxPow_DisChg_B2_09 "汇流排2最大允许放电功率";
CM_ SG_ 2333929114 M2P_PermitMaxVolt_B2_10 "汇流排2最高允许充电电压 （配置量）";
CM_ SG_ 2333929114 M2P_PermitMinVolt_B2_10 "汇流排2最低允许放电电压 （配置量）";
CM_ SG_ 2333929114 M2P_PermitMaxPow_Chg_B2_10 "汇流排2最大允许充电功率";
CM_ SG_ 2333929114 M2P_PermitMaxPow_DisChg_B2_10 "汇流排2最大允许放电功率";
CM_ SG_ 2333929115 M2P_PermitMaxVolt_B2_11 "汇流排2最高允许充电电压 （配置量）";
CM_ SG_ 2333929115 M2P_PermitMinVolt_B2_11 "汇流排2最低允许放电电压 （配置量）";
CM_ SG_ 2333929115 M2P_PermitMaxPow_Chg_B2_11 "汇流排2最大允许充电功率";
CM_ SG_ 2333929115 M2P_PermitMaxPow_DisChg_B2_11 "汇流排2最大允许放电功率";
CM_ SG_ 2333929116 M2P_PermitMaxVolt_B2_12 "汇流排2最高允许充电电压 （配置量）";
CM_ SG_ 2333929116 M2P_PermitMinVolt_B2_12 "汇流排2最低允许放电电压 （配置量）";
CM_ SG_ 2333929116 M2P_PermitMaxPow_Chg_B2_12 "汇流排2最大允许充电功率";
CM_ SG_ 2333929116 M2P_PermitMaxPow_DisChg_B2_12 "汇流排2最大允许放电功率";
CM_ SG_ 2333929117 M2P_PermitMaxVolt_B2_13 "汇流排2最高允许充电电压 （配置量）";
CM_ SG_ 2333929117 M2P_PermitMinVolt_B2_13 "汇流排2最低允许放电电压 （配置量）";
CM_ SG_ 2333929117 M2P_PermitMaxPow_Chg_B2_13 "汇流排2最大允许充电功率";
CM_ SG_ 2333929117 M2P_PermitMaxPow_DisChg_B2_13 "汇流排2最大允许放电功率";
CM_ SG_ 2333929118 M2P_PermitMaxVolt_B2_14 "汇流排2最高允许充电电压 （配置量）";
CM_ SG_ 2333929118 M2P_PermitMinVolt_B2_14 "汇流排2最低允许放电电压 （配置量）";
CM_ SG_ 2333929118 M2P_PermitMaxPow_Chg_B2_14 "汇流排2最大允许充电功率";
CM_ SG_ 2333929118 M2P_PermitMaxPow_DisChg_B2_14 "汇流排2最大允许放电功率";
CM_ SG_ 2333929119 M2P_PermitMaxVolt_B2_15 "汇流排2最高允许充电电压 （配置量）";
CM_ SG_ 2333929119 M2P_PermitMinVolt_B2_15 "汇流排2最低允许放电电压 （配置量）";
CM_ SG_ 2333929119 M2P_PermitMaxPow_Chg_B2_15 "汇流排2最大允许充电功率";
CM_ SG_ 2333929119 M2P_PermitMaxPow_DisChg_B2_15 "汇流排2最大允许放电功率";
CM_ SG_ 2333929120 M2P_PermitMaxVolt_B2_16 "汇流排2最高允许充电电压 （配置量）";
CM_ SG_ 2333929120 M2P_PermitMinVolt_B2_16 "汇流排2最低允许放电电压 （配置量）";
CM_ SG_ 2333929120 M2P_PermitMaxPow_Chg_B2_16 "汇流排2最大允许充电功率";
CM_ SG_ 2333929120 M2P_PermitMaxPow_DisChg_B2_16 "汇流排2最大允许放电功率";
CM_ SG_ 2333929121 M2P_PermitMaxVolt_B2_17 "汇流排2最高允许充电电压 （配置量）";
CM_ SG_ 2333929121 M2P_PermitMinVolt_B2_17 "汇流排2最低允许放电电压 （配置量）";
CM_ SG_ 2333929121 M2P_PermitMaxPow_Chg_B2_17 "汇流排2最大允许充电功率";
CM_ SG_ 2333929121 M2P_PermitMaxPow_DisChg_B2_17 "汇流排2最大允许放电功率";
CM_ SG_ 2333929122 M2P_PermitMaxVolt_B2_18 "汇流排2最高允许充电电压 （配置量）";
CM_ SG_ 2333929122 M2P_PermitMinVolt_B2_18 "汇流排2最低允许放电电压 （配置量）";
CM_ SG_ 2333929122 M2P_PermitMaxPow_Chg_B2_18 "汇流排2最大允许充电功率";
CM_ SG_ 2333929122 M2P_PermitMaxPow_DisChg_B2_18 "汇流排2最大允许放电功率";
CM_ SG_ 2333929123 M2P_PermitMaxVolt_B2_19 "汇流排2最高允许充电电压 （配置量）";
CM_ SG_ 2333929123 M2P_PermitMinVolt_B2_19 "汇流排2最低允许放电电压 （配置量）";
CM_ SG_ 2333929123 M2P_PermitMaxPow_Chg_B2_19 "汇流排2最大允许充电功率";
CM_ SG_ 2333929123 M2P_PermitMaxPow_DisChg_B2_19 "汇流排2最大允许放电功率";
CM_ SG_ 2333929124 M2P_PermitMaxVolt_B2_20 "汇流排2最高允许充电电压 （配置量）";
CM_ SG_ 2333929124 M2P_PermitMinVolt_B2_20 "汇流排2最低允许放电电压 （配置量）";
CM_ SG_ 2333929124 M2P_PermitMaxPow_Chg_B2_20 "汇流排2最大允许充电功率";
CM_ SG_ 2333929124 M2P_PermitMaxPow_DisChg_B2_20 "汇流排2最大允许放电功率";
CM_ SG_ 2333929125 M2P_PermitMaxVolt_B2_21 "汇流排2最高允许充电电压 （配置量）";
CM_ SG_ 2333929125 M2P_PermitMinVolt_B2_21 "汇流排2最低允许放电电压 （配置量）";
CM_ SG_ 2333929125 M2P_PermitMaxPow_Chg_B2_21 "汇流排2最大允许充电功率";
CM_ SG_ 2333929125 M2P_PermitMaxPow_DisChg_B2_21 "汇流排2最大允许放电功率";
CM_ SG_ 2333929126 M2P_PermitMaxVolt_B2_22 "汇流排2最高允许充电电压 （配置量）";
CM_ SG_ 2333929126 M2P_PermitMinVolt_B2_22 "汇流排2最低允许放电电压 （配置量）";
CM_ SG_ 2333929126 M2P_PermitMaxPow_Chg_B2_22 "汇流排2最大允许充电功率";
CM_ SG_ 2333929126 M2P_PermitMaxPow_DisChg_B2_22 "汇流排2最大允许放电功率";
CM_ SG_ 2333929127 M2P_PermitMaxVolt_B2_23 "汇流排2最高允许充电电压 （配置量）";
CM_ SG_ 2333929127 M2P_PermitMinVolt_B2_23 "汇流排2最低允许放电电压 （配置量）";
CM_ SG_ 2333929127 M2P_PermitMaxPow_Chg_B2_23 "汇流排2最大允许充电功率";
CM_ SG_ 2333929127 M2P_PermitMaxPow_DisChg_B2_23 "汇流排2最大允许放电功率";
CM_ SG_ 2333929128 M2P_PermitMaxVolt_B2_24 "汇流排2最高允许充电电压 （配置量）";
CM_ SG_ 2333929128 M2P_PermitMinVolt_B2_24 "汇流排2最低允许放电电压 （配置量）";
CM_ SG_ 2333929128 M2P_PermitMaxPow_Chg_B2_24 "汇流排2最大允许充电功率";
CM_ SG_ 2333929128 M2P_PermitMaxPow_DisChg_B2_24 "汇流排2最大允许放电功率";
CM_ SG_ 2333929129 M2P_PermitMaxVolt_B2_25 "汇流排2最高允许充电电压 （配置量）";
CM_ SG_ 2333929129 M2P_PermitMinVolt_B2_25 "汇流排2最低允许放电电压 （配置量）";
CM_ SG_ 2333929129 M2P_PermitMaxPow_Chg_B2_25 "汇流排2最大允许充电功率";
CM_ SG_ 2333929129 M2P_PermitMaxPow_DisChg_B2_25 "汇流排2最大允许放电功率";
CM_ SG_ 2333929130 M2P_PermitMaxVolt_B2_26 "汇流排2最高允许充电电压 （配置量）";
CM_ SG_ 2333929130 M2P_PermitMinVolt_B2_26 "汇流排2最低允许放电电压 （配置量）";
CM_ SG_ 2333929130 M2P_PermitMaxPow_Chg_B2_26 "汇流排2最大允许充电功率";
CM_ SG_ 2333929130 M2P_PermitMaxPow_DisChg_B2_26 "汇流排2最大允许放电功率";
CM_ SG_ 2333929131 M2P_PermitMaxVolt_B2_27 "汇流排2最高允许充电电压 （配置量）";
CM_ SG_ 2333929131 M2P_PermitMinVolt_B2_27 "汇流排2最低允许放电电压 （配置量）";
CM_ SG_ 2333929131 M2P_PermitMaxPow_Chg_B2_27 "汇流排2最大允许充电功率";
CM_ SG_ 2333929131 M2P_PermitMaxPow_DisChg_B2_27 "汇流排2最大允许放电功率";
CM_ SG_ 2333929132 M2P_PermitMaxVolt_B2_28 "汇流排2最高允许充电电压 （配置量）";
CM_ SG_ 2333929132 M2P_PermitMinVolt_B2_28 "汇流排2最低允许放电电压 （配置量）";
CM_ SG_ 2333929132 M2P_PermitMaxPow_Chg_B2_28 "汇流排2最大允许充电功率";
CM_ SG_ 2333929132 M2P_PermitMaxPow_DisChg_B2_28 "汇流排2最大允许放电功率";
CM_ SG_ 2333929133 M2P_PermitMaxVolt_B2_29 "汇流排2最高允许充电电压 （配置量）";
CM_ SG_ 2333929133 M2P_PermitMinVolt_B2_29 "汇流排2最低允许放电电压 （配置量）";
CM_ SG_ 2333929133 M2P_PermitMaxPow_Chg_B2_29 "汇流排2最大允许充电功率";
CM_ SG_ 2333929133 M2P_PermitMaxPow_DisChg_B2_29 "汇流排2最大允许放电功率";
CM_ SG_ 2333929134 M2P_PermitMaxVolt_B2_30 "汇流排2最高允许充电电压 （配置量）";
CM_ SG_ 2333929134 M2P_PermitMinVolt_B2_30 "汇流排2最低允许放电电压 （配置量）";
CM_ SG_ 2333929134 M2P_PermitMaxPow_Chg_B2_30 "汇流排2最大允许充电功率";
CM_ SG_ 2333929134 M2P_PermitMaxPow_DisChg_B2_30 "汇流排2最大允许放电功率";
CM_ SG_ 2333929135 M2P_PermitMaxVolt_B2_31 "汇流排2最高允许充电电压 （配置量）";
CM_ SG_ 2333929135 M2P_PermitMinVolt_B2_31 "汇流排2最低允许放电电压 （配置量）";
CM_ SG_ 2333929135 M2P_PermitMaxPow_Chg_B2_31 "汇流排2最大允许充电功率";
CM_ SG_ 2333929135 M2P_PermitMaxPow_DisChg_B2_31 "汇流排2最大允许放电功率";
CM_ SG_ 2333994641 M2P_Power_B2_01 "汇流排2实时功率";
CM_ SG_ 2333994641 M2P_SysremEngy_Chg_B2_01 "汇流排2充电剩余能量";
CM_ SG_ 2333994641 M2P_SysremEngy_DisChg_B2_01 "汇流排2放电剩余能量";
CM_ SG_ 2333994641 M2P_SysMaxVolt_B2_01 "汇流排2单体最大电压  ";
CM_ SG_ 2333994642 M2P_Power_B2_02 "汇流排2实时功率";
CM_ SG_ 2333994642 M2P_SysremEngy_Chg_B2_02 "汇流排2充电剩余能量";
CM_ SG_ 2333994642 M2P_SysremEngy_DisChg_B2_02 "汇流排2放电剩余能量";
CM_ SG_ 2333994642 M2P_SysMaxVolt_B2_02 "汇流排2单体最大电压  ";
CM_ SG_ 2333994643 M2P_Power_B2_03 "汇流排2实时功率";
CM_ SG_ 2333994643 M2P_SysremEngy_Chg_B2_03 "汇流排2充电剩余能量";
CM_ SG_ 2333994643 M2P_SysremEngy_DisChg_B2_03 "汇流排2放电剩余能量";
CM_ SG_ 2333994643 M2P_SysMaxVolt_B2_03 "汇流排2单体最大电压  ";
CM_ SG_ 2333994644 M2P_Power_B2_04 "汇流排2实时功率";
CM_ SG_ 2333994644 M2P_SysremEngy_Chg_B2_04 "汇流排2充电剩余能量";
CM_ SG_ 2333994644 M2P_SysremEngy_DisChg_B2_04 "汇流排2放电剩余能量";
CM_ SG_ 2333994644 M2P_SysMaxVolt_B2_04 "汇流排2单体最大电压  ";
CM_ SG_ 2333994645 M2P_Power_B2_05 "汇流排2实时功率";
CM_ SG_ 2333994645 M2P_SysremEngy_Chg_B2_05 "汇流排2充电剩余能量";
CM_ SG_ 2333994645 M2P_SysremEngy_DisChg_B2_05 "汇流排2放电剩余能量";
CM_ SG_ 2333994645 M2P_SysMaxVolt_B2_05 "汇流排2单体最大电压  ";
CM_ SG_ 2333994646 M2P_Power_B2_06 "汇流排2实时功率";
CM_ SG_ 2333994646 M2P_SysremEngy_Chg_B2_06 "汇流排2充电剩余能量";
CM_ SG_ 2333994646 M2P_SysremEngy_DisChg_B2_06 "汇流排2放电剩余能量";
CM_ SG_ 2333994646 M2P_SysMaxVolt_B2_06 "汇流排2单体最大电压  ";
CM_ SG_ 2333994647 M2P_Power_B2_07 "汇流排2实时功率";
CM_ SG_ 2333994647 M2P_SysremEngy_Chg_B2_07 "汇流排2充电剩余能量";
CM_ SG_ 2333994647 M2P_SysremEngy_DisChg_B2_07 "汇流排2放电剩余能量";
CM_ SG_ 2333994647 M2P_SysMaxVolt_B2_07 "汇流排2单体最大电压  ";
CM_ SG_ 2333994648 M2P_Power_B2_08 "汇流排2实时功率";
CM_ SG_ 2333994648 M2P_SysremEngy_Chg_B2_08 "汇流排2充电剩余能量";
CM_ SG_ 2333994648 M2P_SysremEngy_DisChg_B2_08 "汇流排2放电剩余能量";
CM_ SG_ 2333994648 M2P_SysMaxVolt_B2_08 "汇流排2单体最大电压  ";
CM_ SG_ 2333994649 M2P_Power_B2_09 "汇流排2实时功率";
CM_ SG_ 2333994649 M2P_SysremEngy_Chg_B2_09 "汇流排2充电剩余能量";
CM_ SG_ 2333994649 M2P_SysremEngy_DisChg_B2_09 "汇流排2放电剩余能量";
CM_ SG_ 2333994649 M2P_SysMaxVolt_B2_09 "汇流排2单体最大电压  ";
CM_ SG_ 2333994650 M2P_Power_B2_10 "汇流排2实时功率";
CM_ SG_ 2333994650 M2P_SysremEngy_Chg_B2_10 "汇流排2充电剩余能量";
CM_ SG_ 2333994650 M2P_SysremEngy_DisChg_B2_10 "汇流排2放电剩余能量";
CM_ SG_ 2333994650 M2P_SysMaxVolt_B2_10 "汇流排2单体最大电压  ";
CM_ SG_ 2333994651 M2P_Power_B2_11 "汇流排2实时功率";
CM_ SG_ 2333994651 M2P_SysremEngy_Chg_B2_11 "汇流排2充电剩余能量";
CM_ SG_ 2333994651 M2P_SysremEngy_DisChg_B2_11 "汇流排2放电剩余能量";
CM_ SG_ 2333994651 M2P_SysMaxVolt_B2_11 "汇流排2单体最大电压  ";
CM_ SG_ 2333994652 M2P_Power_B2_12 "汇流排2实时功率";
CM_ SG_ 2333994652 M2P_SysremEngy_Chg_B2_12 "汇流排2充电剩余能量";
CM_ SG_ 2333994652 M2P_SysremEngy_DisChg_B2_12 "汇流排2放电剩余能量";
CM_ SG_ 2333994652 M2P_SysMaxVolt_B2_12 "汇流排2单体最大电压  ";
CM_ SG_ 2333994653 M2P_Power_B2_13 "汇流排2实时功率";
CM_ SG_ 2333994653 M2P_SysremEngy_Chg_B2_13 "汇流排2充电剩余能量";
CM_ SG_ 2333994653 M2P_SysremEngy_DisChg_B2_13 "汇流排2放电剩余能量";
CM_ SG_ 2333994653 M2P_SysMaxVolt_B2_13 "汇流排2单体最大电压  ";
CM_ SG_ 2333994654 M2P_Power_B2_14 "汇流排2实时功率";
CM_ SG_ 2333994654 M2P_SysremEngy_Chg_B2_14 "汇流排2充电剩余能量";
CM_ SG_ 2333994654 M2P_SysremEngy_DisChg_B2_14 "汇流排2放电剩余能量";
CM_ SG_ 2333994654 M2P_SysMaxVolt_B2_14 "汇流排2单体最大电压  ";
CM_ SG_ 2333994655 M2P_Power_B2_15 "汇流排2实时功率";
CM_ SG_ 2333994655 M2P_SysremEngy_Chg_B2_15 "汇流排2充电剩余能量";
CM_ SG_ 2333994655 M2P_SysremEngy_DisChg_B2_15 "汇流排2放电剩余能量";
CM_ SG_ 2333994655 M2P_SysMaxVolt_B2_15 "汇流排2单体最大电压  ";
CM_ SG_ 2333994656 M2P_Power_B2_16 "汇流排2实时功率";
CM_ SG_ 2333994656 M2P_SysremEngy_Chg_B2_16 "汇流排2充电剩余能量";
CM_ SG_ 2333994656 M2P_SysremEngy_DisChg_B2_16 "汇流排2放电剩余能量";
CM_ SG_ 2333994656 M2P_SysMaxVolt_B2_16 "汇流排2单体最大电压  ";
CM_ SG_ 2333994657 M2P_Power_B2_17 "汇流排2实时功率";
CM_ SG_ 2333994657 M2P_SysremEngy_Chg_B2_17 "汇流排2充电剩余能量";
CM_ SG_ 2333994657 M2P_SysremEngy_DisChg_B2_17 "汇流排2放电剩余能量";
CM_ SG_ 2333994657 M2P_SysMaxVolt_B2_17 "汇流排2单体最大电压  ";
CM_ SG_ 2333994658 M2P_Power_B2_18 "汇流排2实时功率";
CM_ SG_ 2333994658 M2P_SysremEngy_Chg_B2_18 "汇流排2充电剩余能量";
CM_ SG_ 2333994658 M2P_SysremEngy_DisChg_B2_18 "汇流排2放电剩余能量";
CM_ SG_ 2333994658 M2P_SysMaxVolt_B2_18 "汇流排2单体最大电压  ";
CM_ SG_ 2333994659 M2P_Power_B2_19 "汇流排2实时功率";
CM_ SG_ 2333994659 M2P_SysremEngy_Chg_B2_19 "汇流排2充电剩余能量";
CM_ SG_ 2333994659 M2P_SysremEngy_DisChg_B2_19 "汇流排2放电剩余能量";
CM_ SG_ 2333994659 M2P_SysMaxVolt_B2_19 "汇流排2单体最大电压  ";
CM_ SG_ 2333994660 M2P_Power_B2_20 "汇流排2实时功率";
CM_ SG_ 2333994660 M2P_SysremEngy_Chg_B2_20 "汇流排2充电剩余能量";
CM_ SG_ 2333994660 M2P_SysremEngy_DisChg_B2_20 "汇流排2放电剩余能量";
CM_ SG_ 2333994660 M2P_SysMaxVolt_B2_20 "汇流排2单体最大电压  ";
CM_ SG_ 2333994661 M2P_Power_B2_21 "汇流排2实时功率";
CM_ SG_ 2333994661 M2P_SysremEngy_Chg_B2_21 "汇流排2充电剩余能量";
CM_ SG_ 2333994661 M2P_SysremEngy_DisChg_B2_21 "汇流排2放电剩余能量";
CM_ SG_ 2333994661 M2P_SysMaxVolt_B2_21 "汇流排2单体最大电压  ";
CM_ SG_ 2333994662 M2P_Power_B2_22 "汇流排2实时功率";
CM_ SG_ 2333994662 M2P_SysremEngy_Chg_B2_22 "汇流排2充电剩余能量";
CM_ SG_ 2333994662 M2P_SysremEngy_DisChg_B2_22 "汇流排2放电剩余能量";
CM_ SG_ 2333994662 M2P_SysMaxVolt_B2_22 "汇流排2单体最大电压  ";
CM_ SG_ 2333994663 M2P_Power_B2_23 "汇流排2实时功率";
CM_ SG_ 2333994663 M2P_SysremEngy_Chg_B2_23 "汇流排2充电剩余能量";
CM_ SG_ 2333994663 M2P_SysremEngy_DisChg_B2_23 "汇流排2放电剩余能量";
CM_ SG_ 2333994663 M2P_SysMaxVolt_B2_23 "汇流排2单体最大电压  ";
CM_ SG_ 2333994664 M2P_Power_B2_24 "汇流排2实时功率";
CM_ SG_ 2333994664 M2P_SysremEngy_Chg_B2_24 "汇流排2充电剩余能量";
CM_ SG_ 2333994664 M2P_SysremEngy_DisChg_B2_24 "汇流排2放电剩余能量";
CM_ SG_ 2333994664 M2P_SysMaxVolt_B2_24 "汇流排2单体最大电压  ";
CM_ SG_ 2333994665 M2P_Power_B2_25 "汇流排2实时功率";
CM_ SG_ 2333994665 M2P_SysremEngy_Chg_B2_25 "汇流排2充电剩余能量";
CM_ SG_ 2333994665 M2P_SysremEngy_DisChg_B2_25 "汇流排2放电剩余能量";
CM_ SG_ 2333994665 M2P_SysMaxVolt_B2_25 "汇流排2单体最大电压  ";
CM_ SG_ 2333994666 M2P_Power_B2_26 "汇流排2实时功率";
CM_ SG_ 2333994666 M2P_SysremEngy_Chg_B2_26 "汇流排2充电剩余能量";
CM_ SG_ 2333994666 M2P_SysremEngy_DisChg_B2_26 "汇流排2放电剩余能量";
CM_ SG_ 2333994666 M2P_SysMaxVolt_B2_26 "汇流排2单体最大电压  ";
CM_ SG_ 2333994667 M2P_Power_B2_27 "汇流排2实时功率";
CM_ SG_ 2333994667 M2P_SysremEngy_Chg_B2_27 "汇流排2充电剩余能量";
CM_ SG_ 2333994667 M2P_SysremEngy_DisChg_B2_27 "汇流排2放电剩余能量";
CM_ SG_ 2333994667 M2P_SysMaxVolt_B2_27 "汇流排2单体最大电压  ";
CM_ SG_ 2333994668 M2P_Power_B2_28 "汇流排2实时功率";
CM_ SG_ 2333994668 M2P_SysremEngy_Chg_B2_28 "汇流排2充电剩余能量";
CM_ SG_ 2333994668 M2P_SysremEngy_DisChg_B2_28 "汇流排2放电剩余能量";
CM_ SG_ 2333994668 M2P_SysMaxVolt_B2_28 "汇流排2单体最大电压  ";
CM_ SG_ 2333994669 M2P_Power_B2_29 "汇流排2实时功率";
CM_ SG_ 2333994669 M2P_SysremEngy_Chg_B2_29 "汇流排2充电剩余能量";
CM_ SG_ 2333994669 M2P_SysremEngy_DisChg_B2_29 "汇流排2放电剩余能量";
CM_ SG_ 2333994669 M2P_SysMaxVolt_B2_29 "汇流排2单体最大电压  ";
CM_ SG_ 2333994670 M2P_Power_B2_30 "汇流排2实时功率";
CM_ SG_ 2333994670 M2P_SysremEngy_Chg_B2_30 "汇流排2充电剩余能量";
CM_ SG_ 2333994670 M2P_SysremEngy_DisChg_B2_30 "汇流排2放电剩余能量";
CM_ SG_ 2333994670 M2P_SysMaxVolt_B2_30 "汇流排2单体最大电压  ";
CM_ SG_ 2333994671 M2P_Power_B2_31 "汇流排2实时功率";
CM_ SG_ 2333994671 M2P_SysremEngy_Chg_B2_31 "汇流排2充电剩余能量";
CM_ SG_ 2333994671 M2P_SysremEngy_DisChg_B2_31 "汇流排2放电剩余能量";
CM_ SG_ 2333994671 M2P_SysMaxVolt_B2_31 "汇流排2单体最大电压  ";
CM_ SG_ 2334060177 M2P_SysMinVolt_B2_01 "汇流排2单体最小电压";
CM_ SG_ 2334060177 M2P_SysAvgVolt_B2_01 "汇流排2单体平均电压";
CM_ SG_ 2334060177 M2P_BMS_Status_B2 "汇流排2能量状态";
CM_ SG_ 2334060177 M2P_SOC_B2 "汇流排2系统SOC";
CM_ SG_ 2334060177 M2P_SOH_B2 "汇流排2系统SOH";
CM_ SG_ 2334060177 Reserved_01 "预留";
CM_ SG_ 2334060178 M2P_SysMinVolt_B2_02 "汇流排2单体最小电压";
CM_ SG_ 2334060178 M2P_SysAvgVolt_B2_02 "汇流排2单体平均电压";
CM_ SG_ 2334060178 M2P_BMS_Status_B2 "汇流排2能量状态";
CM_ SG_ 2334060178 M2P_SOC_B2 "汇流排2系统SOC";
CM_ SG_ 2334060178 M2P_SOH_B2 "汇流排2系统SOH";
CM_ SG_ 2334060178 Reserved_02 "预留";
CM_ SG_ 2334060179 M2P_SysMinVolt_B2_03 "汇流排2单体最小电压";
CM_ SG_ 2334060179 M2P_SysAvgVolt_B2_03 "汇流排2单体平均电压";
CM_ SG_ 2334060179 M2P_BMS_Status_B2 "汇流排2能量状态";
CM_ SG_ 2334060179 M2P_SOC_B2 "汇流排2系统SOC";
CM_ SG_ 2334060179 M2P_SOH_B2 "汇流排2系统SOH";
CM_ SG_ 2334060179 Reserved_03 "预留";
CM_ SG_ 2334060180 M2P_SysMinVolt_B2_04 "汇流排2单体最小电压";
CM_ SG_ 2334060180 M2P_SysAvgVolt_B2_04 "汇流排2单体平均电压";
CM_ SG_ 2334060180 M2P_BMS_Status_B2 "汇流排2能量状态";
CM_ SG_ 2334060180 M2P_SOC_B2 "汇流排2系统SOC";
CM_ SG_ 2334060180 M2P_SOH_B2 "汇流排2系统SOH";
CM_ SG_ 2334060180 Reserved_04 "预留";
CM_ SG_ 2334060181 M2P_SysMinVolt_B2_05 "汇流排2单体最小电压";
CM_ SG_ 2334060181 M2P_SysAvgVolt_B2_05 "汇流排2单体平均电压";
CM_ SG_ 2334060181 M2P_BMS_Status_B2 "汇流排2能量状态";
CM_ SG_ 2334060181 M2P_SOC_B2 "汇流排2系统SOC";
CM_ SG_ 2334060181 M2P_SOH_B2 "汇流排2系统SOH";
CM_ SG_ 2334060181 Reserved_05 "预留";
CM_ SG_ 2334060182 M2P_SysMinVolt_B2_06 "汇流排2单体最小电压";
CM_ SG_ 2334060182 M2P_SysAvgVolt_B2_06 "汇流排2单体平均电压";
CM_ SG_ 2334060182 M2P_BMS_Status_B2 "汇流排2能量状态";
CM_ SG_ 2334060182 M2P_SOC_B2 "汇流排2系统SOC";
CM_ SG_ 2334060182 M2P_SOH_B2 "汇流排2系统SOH";
CM_ SG_ 2334060182 Reserved_06 "预留";
CM_ SG_ 2334060183 M2P_SysMinVolt_B2_07 "汇流排2单体最小电压";
CM_ SG_ 2334060183 M2P_SysAvgVolt_B2_07 "汇流排2单体平均电压";
CM_ SG_ 2334060183 M2P_BMS_Status_B2 "汇流排2能量状态";
CM_ SG_ 2334060183 M2P_SOC_B2 "汇流排2系统SOC";
CM_ SG_ 2334060183 M2P_SOH_B2 "汇流排2系统SOH";
CM_ SG_ 2334060183 Reserved_07 "预留";
CM_ SG_ 2334060184 M2P_SysMinVolt_B2_08 "汇流排2单体最小电压";
CM_ SG_ 2334060184 M2P_SysAvgVolt_B2_08 "汇流排2单体平均电压";
CM_ SG_ 2334060184 M2P_BMS_Status_B2 "汇流排2能量状态";
CM_ SG_ 2334060184 M2P_SOC_B2 "汇流排2系统SOC";
CM_ SG_ 2334060184 M2P_SOH_B2 "汇流排2系统SOH";
CM_ SG_ 2334060184 Reserved_08 "预留";
CM_ SG_ 2334060185 M2P_SysMinVolt_B2_09 "汇流排2单体最小电压";
CM_ SG_ 2334060185 M2P_SysAvgVolt_B2_09 "汇流排2单体平均电压";
CM_ SG_ 2334060185 M2P_BMS_Status_B2 "汇流排2能量状态";
CM_ SG_ 2334060185 M2P_SOC_B2 "汇流排2系统SOC";
CM_ SG_ 2334060185 M2P_SOH_B2 "汇流排2系统SOH";
CM_ SG_ 2334060185 Reserved_09 "预留";
CM_ SG_ 2334060186 M2P_SysMinVolt_B2_10 "汇流排2单体最小电压";
CM_ SG_ 2334060186 M2P_SysAvgVolt_B2_10 "汇流排2单体平均电压";
CM_ SG_ 2334060186 M2P_BMS_Status_B2 "汇流排2能量状态";
CM_ SG_ 2334060186 M2P_SOC_B2 "汇流排2系统SOC";
CM_ SG_ 2334060186 M2P_SOH_B2 "汇流排2系统SOH";
CM_ SG_ 2334060186 Reserved_10 "预留";
CM_ SG_ 2334060187 M2P_SysMinVolt_B2_11 "汇流排2单体最小电压";
CM_ SG_ 2334060187 M2P_SysAvgVolt_B2_11 "汇流排2单体平均电压";
CM_ SG_ 2334060187 M2P_BMS_Status_B2 "汇流排2能量状态";
CM_ SG_ 2334060187 M2P_SOC_B2 "汇流排2系统SOC";
CM_ SG_ 2334060187 M2P_SOH_B2 "汇流排2系统SOH";
CM_ SG_ 2334060187 Reserved_11 "预留";
CM_ SG_ 2334060188 M2P_SysMinVolt_B2_12 "汇流排2单体最小电压";
CM_ SG_ 2334060188 M2P_SysAvgVolt_B2_12 "汇流排2单体平均电压";
CM_ SG_ 2334060188 M2P_BMS_Status_B2 "汇流排2能量状态";
CM_ SG_ 2334060188 M2P_SOC_B2 "汇流排2系统SOC";
CM_ SG_ 2334060188 M2P_SOH_B2 "汇流排2系统SOH";
CM_ SG_ 2334060188 Reserved_12 "预留";
CM_ SG_ 2334060189 M2P_SysMinVolt_B2_13 "汇流排2单体最小电压";
CM_ SG_ 2334060189 M2P_SysAvgVolt_B2_13 "汇流排2单体平均电压";
CM_ SG_ 2334060189 M2P_BMS_Status_B2 "汇流排2能量状态";
CM_ SG_ 2334060189 M2P_SOC_B2 "汇流排2系统SOC";
CM_ SG_ 2334060189 M2P_SOH_B2 "汇流排2系统SOH";
CM_ SG_ 2334060189 Reserved_13 "预留";
CM_ SG_ 2334060190 M2P_SysMinVolt_B2_14 "汇流排2单体最小电压";
CM_ SG_ 2334060190 M2P_SysAvgVolt_B2_14 "汇流排2单体平均电压";
CM_ SG_ 2334060190 M2P_BMS_Status_B2 "汇流排2能量状态";
CM_ SG_ 2334060190 M2P_SOC_B2 "汇流排2系统SOC";
CM_ SG_ 2334060190 M2P_SOH_B2 "汇流排2系统SOH";
CM_ SG_ 2334060190 Reserved_14 "预留";
CM_ SG_ 2334060191 M2P_SysMinVolt_B2_15 "汇流排2单体最小电压";
CM_ SG_ 2334060191 M2P_SysAvgVolt_B2_15 "汇流排2单体平均电压";
CM_ SG_ 2334060191 M2P_BMS_Status_B2 "汇流排2能量状态";
CM_ SG_ 2334060191 M2P_SOC_B2 "汇流排2系统SOC";
CM_ SG_ 2334060191 M2P_SOH_B2 "汇流排2系统SOH";
CM_ SG_ 2334060191 Reserved_15 "预留";
CM_ SG_ 2334060192 M2P_SysMinVolt_B2_16 "汇流排2单体最小电压";
CM_ SG_ 2334060192 M2P_SysAvgVolt_B2_16 "汇流排2单体平均电压";
CM_ SG_ 2334060192 M2P_BMS_Status_B2 "汇流排2能量状态";
CM_ SG_ 2334060192 M2P_SOC_B2 "汇流排2系统SOC";
CM_ SG_ 2334060192 M2P_SOH_B2 "汇流排2系统SOH";
CM_ SG_ 2334060192 Reserved_16 "预留";
CM_ SG_ 2334060193 M2P_SysMinVolt_B2_17 "汇流排2单体最小电压";
CM_ SG_ 2334060193 M2P_SysAvgVolt_B2_17 "汇流排2单体平均电压";
CM_ SG_ 2334060193 M2P_BMS_Status_B2 "汇流排2能量状态";
CM_ SG_ 2334060193 M2P_SOC_B2 "汇流排2系统SOC";
CM_ SG_ 2334060193 M2P_SOH_B2 "汇流排2系统SOH";
CM_ SG_ 2334060193 Reserved_17 "预留";
CM_ SG_ 2334060194 M2P_SysMinVolt_B2_18 "汇流排2单体最小电压";
CM_ SG_ 2334060194 M2P_SysAvgVolt_B2_18 "汇流排2单体平均电压";
CM_ SG_ 2334060194 M2P_BMS_Status_B2 "汇流排2能量状态";
CM_ SG_ 2334060194 M2P_SOC_B2 "汇流排2系统SOC";
CM_ SG_ 2334060194 M2P_SOH_B2 "汇流排2系统SOH";
CM_ SG_ 2334060194 Reserved_18 "预留";
CM_ SG_ 2334060195 M2P_SysMinVolt_B2_19 "汇流排2单体最小电压";
CM_ SG_ 2334060195 M2P_SysAvgVolt_B2_19 "汇流排2单体平均电压";
CM_ SG_ 2334060195 M2P_BMS_Status_B2 "汇流排2能量状态";
CM_ SG_ 2334060195 M2P_SOC_B2 "汇流排2系统SOC";
CM_ SG_ 2334060195 M2P_SOH_B2 "汇流排2系统SOH";
CM_ SG_ 2334060195 Reserved_19 "预留";
CM_ SG_ 2334060196 M2P_SysMinVolt_B2_20 "汇流排2单体最小电压";
CM_ SG_ 2334060196 M2P_SysAvgVolt_B2_20 "汇流排2单体平均电压";
CM_ SG_ 2334060196 M2P_BMS_Status_B2 "汇流排2能量状态";
CM_ SG_ 2334060196 M2P_SOC_B2 "汇流排2系统SOC";
CM_ SG_ 2334060196 M2P_SOH_B2 "汇流排2系统SOH";
CM_ SG_ 2334060196 Reserved_20 "预留";
CM_ SG_ 2334060197 M2P_SysMinVolt_B2_21 "汇流排2单体最小电压";
CM_ SG_ 2334060197 M2P_SysAvgVolt_B2_21 "汇流排2单体平均电压";
CM_ SG_ 2334060197 M2P_BMS_Status_B2 "汇流排2能量状态";
CM_ SG_ 2334060197 M2P_SOC_B2 "汇流排2系统SOC";
CM_ SG_ 2334060197 M2P_SOH_B2 "汇流排2系统SOH";
CM_ SG_ 2334060197 Reserved_21 "预留";
CM_ SG_ 2334060198 M2P_SysMinVolt_B2_22 "汇流排2单体最小电压";
CM_ SG_ 2334060198 M2P_SysAvgVolt_B2_22 "汇流排2单体平均电压";
CM_ SG_ 2334060198 M2P_BMS_Status_B2 "汇流排2能量状态";
CM_ SG_ 2334060198 M2P_SOC_B2 "汇流排2系统SOC";
CM_ SG_ 2334060198 M2P_SOH_B2 "汇流排2系统SOH";
CM_ SG_ 2334060198 Reserved_22 "预留";
CM_ SG_ 2334060199 M2P_SysMinVolt_B2_23 "汇流排2单体最小电压";
CM_ SG_ 2334060199 M2P_SysAvgVolt_B2_23 "汇流排2单体平均电压";
CM_ SG_ 2334060199 M2P_BMS_Status_B2 "汇流排2能量状态";
CM_ SG_ 2334060199 M2P_SOC_B2 "汇流排2系统SOC";
CM_ SG_ 2334060199 M2P_SOH_B2 "汇流排2系统SOH";
CM_ SG_ 2334060199 Reserved_23 "预留";
CM_ SG_ 2334060200 M2P_SysMinVolt_B2_24 "汇流排2单体最小电压";
CM_ SG_ 2334060200 M2P_SysAvgVolt_B2_24 "汇流排2单体平均电压";
CM_ SG_ 2334060200 M2P_BMS_Status_B2 "汇流排2能量状态";
CM_ SG_ 2334060200 M2P_SOC_B2 "汇流排2系统SOC";
CM_ SG_ 2334060200 M2P_SOH_B2 "汇流排2系统SOH";
CM_ SG_ 2334060200 Reserved_24 "预留";
CM_ SG_ 2334060201 M2P_SysMinVolt_B2_25 "汇流排2单体最小电压";
CM_ SG_ 2334060201 M2P_SysAvgVolt_B2_25 "汇流排2单体平均电压";
CM_ SG_ 2334060201 M2P_BMS_Status_B2 "汇流排2能量状态";
CM_ SG_ 2334060201 M2P_SOC_B2 "汇流排2系统SOC";
CM_ SG_ 2334060201 M2P_SOH_B2 "汇流排2系统SOH";
CM_ SG_ 2334060201 Reserved_25 "预留";
CM_ SG_ 2334060202 M2P_SysMinVolt_B2_26 "汇流排2单体最小电压";
CM_ SG_ 2334060202 M2P_SysAvgVolt_B2_26 "汇流排2单体平均电压";
CM_ SG_ 2334060202 M2P_BMS_Status_B2 "汇流排2能量状态";
CM_ SG_ 2334060202 M2P_SOC_B2 "汇流排2系统SOC";
CM_ SG_ 2334060202 M2P_SOH_B2 "汇流排2系统SOH";
CM_ SG_ 2334060202 Reserved_26 "预留";
CM_ SG_ 2334060203 M2P_SysMinVolt_B2_27 "汇流排2单体最小电压";
CM_ SG_ 2334060203 M2P_SysAvgVolt_B2_27 "汇流排2单体平均电压";
CM_ SG_ 2334060203 M2P_BMS_Status_B2 "汇流排2能量状态";
CM_ SG_ 2334060203 M2P_SOC_B2 "汇流排2系统SOC";
CM_ SG_ 2334060203 M2P_SOH_B2 "汇流排2系统SOH";
CM_ SG_ 2334060203 Reserved_27 "预留";
CM_ SG_ 2334060204 M2P_SysMinVolt_B2_28 "汇流排2单体最小电压";
CM_ SG_ 2334060204 M2P_SysAvgVolt_B2_28 "汇流排2单体平均电压";
CM_ SG_ 2334060204 M2P_BMS_Status_B2 "汇流排2能量状态";
CM_ SG_ 2334060204 M2P_SOC_B2 "汇流排2系统SOC";
CM_ SG_ 2334060204 M2P_SOH_B2 "汇流排2系统SOH";
CM_ SG_ 2334060204 Reserved_28 "预留";
CM_ SG_ 2334060205 M2P_SysMinVolt_B2_29 "汇流排2单体最小电压";
CM_ SG_ 2334060205 M2P_SysAvgVolt_B2_29 "汇流排2单体平均电压";
CM_ SG_ 2334060205 M2P_BMS_Status_B2 "汇流排2能量状态";
CM_ SG_ 2334060205 M2P_SOC_B2 "汇流排2系统SOC";
CM_ SG_ 2334060205 M2P_SOH_B2 "汇流排2系统SOH";
CM_ SG_ 2334060205 Reserved_29 "预留";
CM_ SG_ 2334060206 M2P_SysMinVolt_B2_30 "汇流排2单体最小电压";
CM_ SG_ 2334060206 M2P_SysAvgVolt_B2_30 "汇流排2单体平均电压";
CM_ SG_ 2334060206 M2P_BMS_Status_B2 "汇流排2能量状态";
CM_ SG_ 2334060206 M2P_SOC_B2 "汇流排2系统SOC";
CM_ SG_ 2334060206 M2P_SOH_B2 "汇流排2系统SOH";
CM_ SG_ 2334060206 Reserved_30 "预留";
CM_ SG_ 2334060207 M2P_SysMinVolt_B2_31 "汇流排2单体最小电压";
CM_ SG_ 2334060207 M2P_SysAvgVolt_B2_31 "汇流排2单体平均电压";
CM_ SG_ 2334060207 M2P_BMS_Status_B2 "汇流排2能量状态";
CM_ SG_ 2334060207 M2P_SOC_B2 "汇流排2系统SOC";
CM_ SG_ 2334060207 M2P_SOH_B2 "汇流排2系统SOH";
CM_ SG_ 2334060207 Reserved_31 "预留";
CM_ SG_ 2334125713 M2P_SOE_Charge_B2 "汇流排2系可充电SOE";
CM_ SG_ 2334125713 M2P_SOE_Discharge_B2 "汇流排2系可放电SOE";
CM_ SG_ 2334125713 Reserved_01 "预留";
CM_ SG_ 2334125714 M2P_SOE_Charge_B2 "汇流排2系可充电SOE";
CM_ SG_ 2334125714 M2P_SOE_Discharge_B2 "汇流排2系可放电SOE";
CM_ SG_ 2334125714 Reserved_02 "预留";
CM_ SG_ 2334125715 M2P_SOE_Charge_B2 "汇流排2系可充电SOE";
CM_ SG_ 2334125715 M2P_SOE_Discharge_B2 "汇流排2系可放电SOE";
CM_ SG_ 2334125715 Reserved_03 "预留";
CM_ SG_ 2334125716 M2P_SOE_Charge_B2 "汇流排2系可充电SOE";
CM_ SG_ 2334125716 M2P_SOE_Discharge_B2 "汇流排2系可放电SOE";
CM_ SG_ 2334125716 Reserved_04 "预留";
CM_ SG_ 2334125717 M2P_SOE_Charge_B2 "汇流排2系可充电SOE";
CM_ SG_ 2334125717 M2P_SOE_Discharge_B2 "汇流排2系可放电SOE";
CM_ SG_ 2334125717 Reserved_05 "预留";
CM_ SG_ 2334125718 M2P_SOE_Charge_B2 "汇流排2系可充电SOE";
CM_ SG_ 2334125718 M2P_SOE_Discharge_B2 "汇流排2系可放电SOE";
CM_ SG_ 2334125718 Reserved_06 "预留";
CM_ SG_ 2334125719 M2P_SOE_Charge_B2 "汇流排2系可充电SOE";
CM_ SG_ 2334125719 M2P_SOE_Discharge_B2 "汇流排2系可放电SOE";
CM_ SG_ 2334125719 Reserved_07 "预留";
CM_ SG_ 2334125720 M2P_SOE_Charge_B2 "汇流排2系可充电SOE";
CM_ SG_ 2334125720 M2P_SOE_Discharge_B2 "汇流排2系可放电SOE";
CM_ SG_ 2334125720 Reserved_08 "预留";
CM_ SG_ 2334125721 M2P_SOE_Charge_B2 "汇流排2系可充电SOE";
CM_ SG_ 2334125721 M2P_SOE_Discharge_B2 "汇流排2系可放电SOE";
CM_ SG_ 2334125721 Reserved_09 "预留";
CM_ SG_ 2334125722 M2P_SOE_Charge_B2 "汇流排2系可充电SOE";
CM_ SG_ 2334125722 M2P_SOE_Discharge_B2 "汇流排2系可放电SOE";
CM_ SG_ 2334125722 Reserved_10 "预留";
CM_ SG_ 2334125723 M2P_SOE_Charge_B2 "汇流排2系可充电SOE";
CM_ SG_ 2334125723 M2P_SOE_Discharge_B2 "汇流排2系可放电SOE";
CM_ SG_ 2334125723 Reserved_11 "预留";
CM_ SG_ 2334125724 M2P_SOE_Charge_B2 "汇流排2系可充电SOE";
CM_ SG_ 2334125724 M2P_SOE_Discharge_B2 "汇流排2系可放电SOE";
CM_ SG_ 2334125724 Reserved_12 "预留";
CM_ SG_ 2334125725 M2P_SOE_Charge_B2 "汇流排2系可充电SOE";
CM_ SG_ 2334125725 M2P_SOE_Discharge_B2 "汇流排2系可放电SOE";
CM_ SG_ 2334125725 Reserved_13 "预留";
CM_ SG_ 2334125726 M2P_SOE_Charge_B2 "汇流排2系可充电SOE";
CM_ SG_ 2334125726 M2P_SOE_Discharge_B2 "汇流排2系可放电SOE";
CM_ SG_ 2334125726 Reserved_14 "预留";
CM_ SG_ 2334125727 M2P_SOE_Charge_B2 "汇流排2系可充电SOE";
CM_ SG_ 2334125727 M2P_SOE_Discharge_B2 "汇流排2系可放电SOE";
CM_ SG_ 2334125727 Reserved_15 "预留";
CM_ SG_ 2334125728 M2P_SOE_Charge_B2 "汇流排2系可充电SOE";
CM_ SG_ 2334125728 M2P_SOE_Discharge_B2 "汇流排2系可放电SOE";
CM_ SG_ 2334125728 Reserved_16 "预留";
CM_ SG_ 2334125729 M2P_SOE_Charge_B2 "汇流排2系可充电SOE";
CM_ SG_ 2334125729 M2P_SOE_Discharge_B2 "汇流排2系可放电SOE";
CM_ SG_ 2334125729 Reserved_17 "预留";
CM_ SG_ 2334125730 M2P_SOE_Charge_B2 "汇流排2系可充电SOE";
CM_ SG_ 2334125730 M2P_SOE_Discharge_B2 "汇流排2系可放电SOE";
CM_ SG_ 2334125730 Reserved_18 "预留";
CM_ SG_ 2334125731 M2P_SOE_Charge_B2 "汇流排2系可充电SOE";
CM_ SG_ 2334125731 M2P_SOE_Discharge_B2 "汇流排2系可放电SOE";
CM_ SG_ 2334125731 Reserved_19 "预留";
CM_ SG_ 2334125732 M2P_SOE_Charge_B2 "汇流排2系可充电SOE";
CM_ SG_ 2334125732 M2P_SOE_Discharge_B2 "汇流排2系可放电SOE";
CM_ SG_ 2334125732 Reserved_20 "预留";
CM_ SG_ 2334125733 M2P_SOE_Charge_B2 "汇流排2系可充电SOE";
CM_ SG_ 2334125733 M2P_SOE_Discharge_B2 "汇流排2系可放电SOE";
CM_ SG_ 2334125733 Reserved_21 "预留";
CM_ SG_ 2334125734 M2P_SOE_Charge_B2 "汇流排2系可充电SOE";
CM_ SG_ 2334125734 M2P_SOE_Discharge_B2 "汇流排2系可放电SOE";
CM_ SG_ 2334125734 Reserved_22 "预留";
CM_ SG_ 2334125735 M2P_SOE_Charge_B2 "汇流排2系可充电SOE";
CM_ SG_ 2334125735 M2P_SOE_Discharge_B2 "汇流排2系可放电SOE";
CM_ SG_ 2334125735 Reserved_23 "预留";
CM_ SG_ 2334125736 M2P_SOE_Charge_B2 "汇流排2系可充电SOE";
CM_ SG_ 2334125736 M2P_SOE_Discharge_B2 "汇流排2系可放电SOE";
CM_ SG_ 2334125736 Reserved_24 "预留";
CM_ SG_ 2334125737 M2P_SOE_Charge_B2 "汇流排2系可充电SOE";
CM_ SG_ 2334125737 M2P_SOE_Discharge_B2 "汇流排2系可放电SOE";
CM_ SG_ 2334125737 Reserved_25 "预留";
CM_ SG_ 2334125738 M2P_SOE_Charge_B2 "汇流排2系可充电SOE";
CM_ SG_ 2334125738 M2P_SOE_Discharge_B2 "汇流排2系可放电SOE";
CM_ SG_ 2334125738 Reserved_26 "预留";
CM_ SG_ 2334125739 M2P_SOE_Charge_B2 "汇流排2系可充电SOE";
CM_ SG_ 2334125739 M2P_SOE_Discharge_B2 "汇流排2系可放电SOE";
CM_ SG_ 2334125739 Reserved_27 "预留";
CM_ SG_ 2334125740 M2P_SOE_Charge_B2 "汇流排2系可充电SOE";
CM_ SG_ 2334125740 M2P_SOE_Discharge_B2 "汇流排2系可放电SOE";
CM_ SG_ 2334125740 Reserved_28 "预留";
CM_ SG_ 2334125741 M2P_SOE_Charge_B2 "汇流排2系可充电SOE";
CM_ SG_ 2334125741 M2P_SOE_Discharge_B2 "汇流排2系可放电SOE";
CM_ SG_ 2334125741 Reserved_29 "预留";
CM_ SG_ 2334125742 M2P_SOE_Charge_B2 "汇流排2系可充电SOE";
CM_ SG_ 2334125742 M2P_SOE_Discharge_B2 "汇流排2系可放电SOE";
CM_ SG_ 2334125742 Reserved_30 "预留";
CM_ SG_ 2334125743 M2P_SOE_Charge_B2 "汇流排2系可充电SOE";
CM_ SG_ 2334125743 M2P_SOE_Discharge_B2 "汇流排2系可放电SOE";
CM_ SG_ 2334125743 Reserved_31 "预留";
VAL_ 2333535917 M2P_Measure_Vol_B1_29 65535 "Invalid" ;
VAL_ 2333535917 M2P_Current_B1_29 65535 "Invalid" ;
VAL_ 2333535917 M2P_PermitMaxCharge_I_B1_29 65535 "Invalid" ;
VAL_ 2333535917 M2P_PermitMaxDisCharge_I_B1_29 65535 "Invalid" ;
VAL_ 2333535918 M2P_Measure_Vol_B1_30 65535 "Invalid" ;
VAL_ 2333535918 M2P_Current_B1_30 65535 "Invalid" ;
VAL_ 2333535918 M2P_PermitMaxCharge_I_B1_30 65535 "Invalid" ;
VAL_ 2333535918 M2P_PermitMaxDisCharge_I_B1_30 65535 "Invalid" ;
VAL_ 2333535919 M2P_Measure_Vol_B1_31 65535 "Invalid" ;
VAL_ 2333535919 M2P_Current_B1_31 65535 "Invalid" ;
VAL_ 2333535919 M2P_PermitMaxCharge_I_B1_31 65535 "Invalid" ;
VAL_ 2333535919 M2P_PermitMaxDisCharge_I_B1_31 65535 "Invalid" ;
VAL_ 2333666961 M2P_SysremEngy_Chg_B1_01 65535 "Invalid" ;
VAL_ 2333666961 M2P_SysremEngy_DisChg_B1_01 65535 "Invalid" ;
VAL_ 2333666962 M2P_SysremEngy_Chg_B1_02 65535 "Invalid" ;
VAL_ 2333666962 M2P_SysremEngy_DisChg_B1_02 65535 "Invalid" ;
VAL_ 2333666963 M2P_SysremEngy_Chg_B1_03 65535 "Invalid" ;
VAL_ 2333666963 M2P_SysremEngy_DisChg_B1_03 65535 "Invalid" ;
VAL_ 2333666964 M2P_SysremEngy_Chg_B1_04 65535 "Invalid" ;
VAL_ 2333666964 M2P_SysremEngy_DisChg_B1_04 65535 "Invalid" ;
VAL_ 2333666965 M2P_SysremEngy_Chg_B1_05 65535 "Invalid" ;
VAL_ 2333666965 M2P_SysremEngy_DisChg_B1_05 65535 "Invalid" ;
VAL_ 2333666966 M2P_SysremEngy_Chg_B1_06 65535 "Invalid" ;
VAL_ 2333666966 M2P_SysremEngy_DisChg_B1_06 65535 "Invalid" ;
VAL_ 2333666967 M2P_SysremEngy_Chg_B1_07 65535 "Invalid" ;
VAL_ 2333666967 M2P_SysremEngy_DisChg_B1_07 65535 "Invalid" ;
VAL_ 2333666968 M2P_SysremEngy_Chg_B1_08 65535 "Invalid" ;
VAL_ 2333666968 M2P_SysremEngy_DisChg_B1_08 65535 "Invalid" ;
VAL_ 2333666969 M2P_SysremEngy_Chg_B1_09 65535 "Invalid" ;
VAL_ 2333666969 M2P_SysremEngy_DisChg_B1_09 65535 "Invalid" ;
VAL_ 2333666970 M2P_SysremEngy_Chg_B1_10 65535 "Invalid" ;
VAL_ 2333666970 M2P_SysremEngy_DisChg_B1_10 65535 "Invalid" ;
VAL_ 2333666971 M2P_SysremEngy_Chg_B1_11 65535 "Invalid" ;
VAL_ 2333666971 M2P_SysremEngy_DisChg_B1_11 65535 "Invalid" ;
VAL_ 2333666972 M2P_SysremEngy_Chg_B1_12 65535 "Invalid" ;
VAL_ 2333666972 M2P_SysremEngy_DisChg_B1_12 65535 "Invalid" ;
VAL_ 2333666973 M2P_SysremEngy_Chg_B1_13 65535 "Invalid" ;
VAL_ 2333666973 M2P_SysremEngy_DisChg_B1_13 65535 "Invalid" ;
VAL_ 2333666974 M2P_SysremEngy_Chg_B1_14 65535 "Invalid" ;
VAL_ 2333666974 M2P_SysremEngy_DisChg_B1_14 65535 "Invalid" ;
VAL_ 2333666975 M2P_SysremEngy_Chg_B1_15 65535 "Invalid" ;
VAL_ 2333666975 M2P_SysremEngy_DisChg_B1_15 65535 "Invalid" ;
VAL_ 2333666976 M2P_SysremEngy_Chg_B1_16 65535 "Invalid" ;
VAL_ 2333666976 M2P_SysremEngy_DisChg_B1_16 65535 "Invalid" ;
VAL_ 2333666977 M2P_SysremEngy_Chg_B1_17 65535 "Invalid" ;
VAL_ 2333666977 M2P_SysremEngy_DisChg_B1_17 65535 "Invalid" ;
VAL_ 2333666978 M2P_SysremEngy_Chg_B1_18 65535 "Invalid" ;
VAL_ 2333666978 M2P_SysremEngy_DisChg_B1_18 65535 "Invalid" ;
VAL_ 2333666979 M2P_SysremEngy_Chg_B1_19 65535 "Invalid" ;
VAL_ 2333666979 M2P_SysremEngy_DisChg_B1_19 65535 "Invalid" ;
VAL_ 2333666980 M2P_SysremEngy_Chg_B1_20 65535 "Invalid" ;
VAL_ 2333666980 M2P_SysremEngy_DisChg_B1_20 65535 "Invalid" ;
VAL_ 2333666981 M2P_SysremEngy_Chg_B1_21 65535 "Invalid" ;
VAL_ 2333666981 M2P_SysremEngy_DisChg_B1_21 65535 "Invalid" ;
VAL_ 2333666982 M2P_SysremEngy_Chg_B1_22 65535 "Invalid" ;
VAL_ 2333666982 M2P_SysremEngy_DisChg_B1_22 65535 "Invalid" ;
VAL_ 2333666983 M2P_SysremEngy_Chg_B1_23 65535 "Invalid" ;
VAL_ 2333666983 M2P_SysremEngy_DisChg_B1_23 65535 "Invalid" ;
VAL_ 2333666984 M2P_SysremEngy_Chg_B1_24 65535 "Invalid" ;
VAL_ 2333666984 M2P_SysremEngy_DisChg_B1_24 65535 "Invalid" ;
VAL_ 2333666985 M2P_SysremEngy_Chg_B1_25 65535 "Invalid" ;
VAL_ 2333666985 M2P_SysremEngy_DisChg_B1_25 65535 "Invalid" ;
VAL_ 2333666986 M2P_SysremEngy_Chg_B1_26 65535 "Invalid" ;
VAL_ 2333666986 M2P_SysremEngy_DisChg_B1_26 65535 "Invalid" ;
VAL_ 2333666987 M2P_SysremEngy_Chg_B1_27 65535 "Invalid" ;
VAL_ 2333666987 M2P_SysremEngy_DisChg_B1_27 65535 "Invalid" ;
VAL_ 2333666988 M2P_SysremEngy_Chg_B1_28 65535 "Invalid" ;
VAL_ 2333666988 M2P_SysremEngy_DisChg_B1_28 65535 "Invalid" ;
VAL_ 2333666989 M2P_SysremEngy_Chg_B1_29 65535 "Invalid" ;
VAL_ 2333666989 M2P_SysremEngy_DisChg_B1_29 65535 "Invalid" ;
VAL_ 2333666990 M2P_SysremEngy_Chg_B1_30 65535 "Invalid" ;
VAL_ 2333666990 M2P_SysremEngy_DisChg_B1_30 65535 "Invalid" ;
VAL_ 2333666991 M2P_SysremEngy_Chg_B1_31 65535 "Invalid" ;
VAL_ 2333666991 M2P_SysremEngy_DisChg_B1_31 65535 "Invalid" ;
VAL_ 2333732497 M2P_BMS_Status_B1 0 "初始化状态" 1 "非满充满放状态" 2 "满充状态" 3 "满放状态" ;
VAL_ 2333732497 M2P_SOC_B1 1023 "Null" ;
VAL_ 2333732497 M2P_SOH_B1 255 "Null" ;
VAL_ 2333732498 M2P_BMS_Status_B1 0 "初始化状态" 1 "非满充满放状态" 2 "满充状态" 3 "满放状态" ;
VAL_ 2333732498 M2P_SOC_B1 1023 "Null" ;
VAL_ 2333732498 M2P_SOH_B1 255 "Null" ;
VAL_ 2333732499 M2P_BMS_Status_B1 0 "初始化状态" 1 "非满充满放状态" 2 "满充状态" 3 "满放状态" ;
VAL_ 2333732499 M2P_SOC_B1 1023 "Null" ;
VAL_ 2333732499 M2P_SOH_B1 255 "Null" ;
VAL_ 2333732500 M2P_BMS_Status_B1 0 "初始化状态" 1 "非满充满放状态" 2 "满充状态" 3 "满放状态" ;
VAL_ 2333732500 M2P_SOC_B1 1023 "Null" ;
VAL_ 2333732500 M2P_SOH_B1 255 "Null" ;
VAL_ 2333732501 M2P_BMS_Status_B1 0 "初始化状态" 1 "非满充满放状态" 2 "满充状态" 3 "满放状态" ;
VAL_ 2333732501 M2P_SOC_B1 1023 "Null" ;
VAL_ 2333732501 M2P_SOH_B1 255 "Null" ;
VAL_ 2333732502 M2P_BMS_Status_B1 0 "初始化状态" 1 "非满充满放状态" 2 "满充状态" 3 "满放状态" ;
VAL_ 2333732502 M2P_SOC_B1 1023 "Null" ;
VAL_ 2333732502 M2P_SOH_B1 255 "Null" ;
VAL_ 2333732503 M2P_BMS_Status_B1 0 "初始化状态" 1 "非满充满放状态" 2 "满充状态" 3 "满放状态" ;
VAL_ 2333732503 M2P_SOC_B1 1023 "Null" ;
VAL_ 2333732503 M2P_SOH_B1 255 "Null" ;
VAL_ 2333732504 M2P_BMS_Status_B1 0 "初始化状态" 1 "非满充满放状态" 2 "满充状态" 3 "满放状态" ;
VAL_ 2333732504 M2P_SOC_B1 1023 "Null" ;
VAL_ 2333732504 M2P_SOH_B1 255 "Null" ;
VAL_ 2333732505 M2P_BMS_Status_B1 0 "初始化状态" 1 "非满充满放状态" 2 "满充状态" 3 "满放状态" ;
VAL_ 2333732505 M2P_SOC_B1 1023 "Null" ;
VAL_ 2333732505 M2P_SOH_B1 255 "Null" ;
VAL_ 2333732506 M2P_BMS_Status_B1 0 "初始化状态" 1 "非满充满放状态" 2 "满充状态" 3 "满放状态" ;
VAL_ 2333732506 M2P_SOC_B1 1023 "Null" ;
VAL_ 2333732506 M2P_SOH_B1 255 "Null" ;
VAL_ 2333732507 M2P_BMS_Status_B1 0 "初始化状态" 1 "非满充满放状态" 2 "满充状态" 3 "满放状态" ;
VAL_ 2333732507 M2P_SOC_B1 1023 "Null" ;
VAL_ 2333732507 M2P_SOH_B1 255 "Null" ;
VAL_ 2333732508 M2P_BMS_Status_B1 0 "初始化状态" 1 "非满充满放状态" 2 "满充状态" 3 "满放状态" ;
VAL_ 2333732508 M2P_SOC_B1 1023 "Null" ;
VAL_ 2333732508 M2P_SOH_B1 255 "Null" ;
VAL_ 2333732509 M2P_BMS_Status_B1 0 "初始化状态" 1 "非满充满放状态" 2 "满充状态" 3 "满放状态" ;
VAL_ 2333732509 M2P_SOC_B1 1023 "Null" ;
VAL_ 2333732509 M2P_SOH_B1 255 "Null" ;
VAL_ 2333732510 M2P_BMS_Status_B1 0 "初始化状态" 1 "非满充满放状态" 2 "满充状态" 3 "满放状态" ;
VAL_ 2333732510 M2P_SOC_B1 1023 "Null" ;
VAL_ 2333732510 M2P_SOH_B1 255 "Null" ;
VAL_ 2333732511 M2P_BMS_Status_B1 0 "初始化状态" 1 "非满充满放状态" 2 "满充状态" 3 "满放状态" ;
VAL_ 2333732511 M2P_SOC_B1 1023 "Null" ;
VAL_ 2333732511 M2P_SOH_B1 255 "Null" ;
VAL_ 2333732512 M2P_BMS_Status_B1 0 "初始化状态" 1 "非满充满放状态" 2 "满充状态" 3 "满放状态" ;
VAL_ 2333732512 M2P_SOC_B1 1023 "Null" ;
VAL_ 2333732512 M2P_SOH_B1 255 "Null" ;
VAL_ 2333732513 M2P_BMS_Status_B1 0 "初始化状态" 1 "非满充满放状态" 2 "满充状态" 3 "满放状态" ;
VAL_ 2333732513 M2P_SOC_B1 1023 "Null" ;
VAL_ 2333732513 M2P_SOH_B1 255 "Null" ;
VAL_ 2333732514 M2P_BMS_Status_B1 0 "初始化状态" 1 "非满充满放状态" 2 "满充状态" 3 "满放状态" ;
VAL_ 2333732514 M2P_SOC_B1 1023 "Null" ;
VAL_ 2333732514 M2P_SOH_B1 255 "Null" ;
VAL_ 2333732515 M2P_BMS_Status_B1 0 "初始化状态" 1 "非满充满放状态" 2 "满充状态" 3 "满放状态" ;
VAL_ 2333732515 M2P_SOC_B1 1023 "Null" ;
VAL_ 2333732515 M2P_SOH_B1 255 "Null" ;
VAL_ 2333732516 M2P_BMS_Status_B1 0 "初始化状态" 1 "非满充满放状态" 2 "满充状态" 3 "满放状态" ;
VAL_ 2333732516 M2P_SOC_B1 1023 "Null" ;
VAL_ 2333732516 M2P_SOH_B1 255 "Null" ;
VAL_ 2333732517 M2P_BMS_Status_B1 0 "初始化状态" 1 "非满充满放状态" 2 "满充状态" 3 "满放状态" ;
VAL_ 2333732517 M2P_SOC_B1 1023 "Null" ;
VAL_ 2333732517 M2P_SOH_B1 255 "Null" ;
VAL_ 2333732518 M2P_BMS_Status_B1 0 "初始化状态" 1 "非满充满放状态" 2 "满充状态" 3 "满放状态" ;
VAL_ 2333732518 M2P_SOC_B1 1023 "Null" ;
VAL_ 2333732518 M2P_SOH_B1 255 "Null" ;
VAL_ 2333732519 M2P_BMS_Status_B1 0 "初始化状态" 1 "非满充满放状态" 2 "满充状态" 3 "满放状态" ;
VAL_ 2333732519 M2P_SOC_B1 1023 "Null" ;
VAL_ 2333732519 M2P_SOH_B1 255 "Null" ;
VAL_ 2333732520 M2P_BMS_Status_B1 0 "初始化状态" 1 "非满充满放状态" 2 "满充状态" 3 "满放状态" ;
VAL_ 2333732520 M2P_SOC_B1 1023 "Null" ;
VAL_ 2333732520 M2P_SOH_B1 255 "Null" ;
VAL_ 2333732521 M2P_BMS_Status_B1 0 "初始化状态" 1 "非满充满放状态" 2 "满充状态" 3 "满放状态" ;
VAL_ 2333732521 M2P_SOC_B1 1023 "Null" ;
VAL_ 2333732521 M2P_SOH_B1 255 "Null" ;
VAL_ 2333732522 M2P_BMS_Status_B1 0 "初始化状态" 1 "非满充满放状态" 2 "满充状态" 3 "满放状态" ;
VAL_ 2333732522 M2P_SOC_B1 1023 "Null" ;
VAL_ 2333732522 M2P_SOH_B1 255 "Null" ;
VAL_ 2333732523 M2P_BMS_Status_B1 0 "初始化状态" 1 "非满充满放状态" 2 "满充状态" 3 "满放状态" ;
VAL_ 2333732523 M2P_SOC_B1 1023 "Null" ;
VAL_ 2333732523 M2P_SOH_B1 255 "Null" ;
VAL_ 2333732524 M2P_BMS_Status_B1 0 "初始化状态" 1 "非满充满放状态" 2 "满充状态" 3 "满放状态" ;
VAL_ 2333732524 M2P_SOC_B1 1023 "Null" ;
VAL_ 2333732524 M2P_SOH_B1 255 "Null" ;
VAL_ 2333732525 M2P_BMS_Status_B1 0 "初始化状态" 1 "非满充满放状态" 2 "满充状态" 3 "满放状态" ;
VAL_ 2333732525 M2P_SOC_B1 1023 "Null" ;
VAL_ 2333732525 M2P_SOH_B1 255 "Null" ;
VAL_ 2333732526 M2P_BMS_Status_B1 0 "初始化状态" 1 "非满充满放状态" 2 "满充状态" 3 "满放状态" ;
VAL_ 2333732526 M2P_SOC_B1 1023 "Null" ;
VAL_ 2333732526 M2P_SOH_B1 255 "Null" ;
VAL_ 2333732527 M2P_BMS_Status_B1 0 "初始化状态" 1 "非满充满放状态" 2 "满充状态" 3 "满放状态" ;
VAL_ 2333732527 M2P_SOC_B1 1023 "Null" ;
VAL_ 2333732527 M2P_SOH_B1 255 "Null" ;
VAL_ 2333798033 M2P_SOE_Charge_B1 1023 "Null" ;
VAL_ 2333798033 M2P_SOE_Discharge_B1 1023 "Null" ;
VAL_ 2333798034 M2P_SOE_Charge_B1 1023 "Null" ;
VAL_ 2333798034 M2P_SOE_Discharge_B1 1023 "Null" ;
VAL_ 2333798035 M2P_SOE_Charge_B1 1023 "Null" ;
VAL_ 2333798035 M2P_SOE_Discharge_B1 1023 "Null" ;
VAL_ 2333798036 M2P_SOE_Charge_B1 1023 "Null" ;
VAL_ 2333798036 M2P_SOE_Discharge_B1 1023 "Null" ;
VAL_ 2333798037 M2P_SOE_Charge_B1 1023 "Null" ;
VAL_ 2333798037 M2P_SOE_Discharge_B1 1023 "Null" ;
VAL_ 2333798038 M2P_SOE_Charge_B1 1023 "Null" ;
VAL_ 2333798038 M2P_SOE_Discharge_B1 1023 "Null" ;
VAL_ 2333798039 M2P_SOE_Charge_B1 1023 "Null" ;
VAL_ 2333798039 M2P_SOE_Discharge_B1 1023 "Null" ;
VAL_ 2333798040 M2P_SOE_Charge_B1 1023 "Null" ;
VAL_ 2333798040 M2P_SOE_Discharge_B1 1023 "Null" ;
VAL_ 2333798041 M2P_SOE_Charge_B1 1023 "Null" ;
VAL_ 2333798041 M2P_SOE_Discharge_B1 1023 "Null" ;
VAL_ 2333798042 M2P_SOE_Charge_B1 1023 "Null" ;
VAL_ 2333798042 M2P_SOE_Discharge_B1 1023 "Null" ;
VAL_ 2333798043 M2P_SOE_Charge_B1 1023 "Null" ;
VAL_ 2333798043 M2P_SOE_Discharge_B1 1023 "Null" ;
VAL_ 2333798044 M2P_SOE_Charge_B1 1023 "Null" ;
VAL_ 2333798044 M2P_SOE_Discharge_B1 1023 "Null" ;
VAL_ 2333798045 M2P_SOE_Charge_B1 1023 "Null" ;
VAL_ 2333798045 M2P_SOE_Discharge_B1 1023 "Null" ;
VAL_ 2333798046 M2P_SOE_Charge_B1 1023 "Null" ;
VAL_ 2333798046 M2P_SOE_Discharge_B1 1023 "Null" ;
VAL_ 2333798047 M2P_SOE_Charge_B1 1023 "Null" ;
VAL_ 2333798047 M2P_SOE_Discharge_B1 1023 "Null" ;
VAL_ 2333798048 M2P_SOE_Charge_B1 1023 "Null" ;
VAL_ 2333798048 M2P_SOE_Discharge_B1 1023 "Null" ;
VAL_ 2333798049 M2P_SOE_Charge_B1 1023 "Null" ;
VAL_ 2333798049 M2P_SOE_Discharge_B1 1023 "Null" ;
VAL_ 2333798050 M2P_SOE_Charge_B1 1023 "Null" ;
VAL_ 2333798050 M2P_SOE_Discharge_B1 1023 "Null" ;
VAL_ 2333798051 M2P_SOE_Charge_B1 1023 "Null" ;
VAL_ 2333798051 M2P_SOE_Discharge_B1 1023 "Null" ;
VAL_ 2333798052 M2P_SOE_Charge_B1 1023 "Null" ;
VAL_ 2333798052 M2P_SOE_Discharge_B1 1023 "Null" ;
VAL_ 2333798053 M2P_SOE_Charge_B1 1023 "Null" ;
VAL_ 2333798053 M2P_SOE_Discharge_B1 1023 "Null" ;
VAL_ 2333798054 M2P_SOE_Charge_B1 1023 "Null" ;
VAL_ 2333798054 M2P_SOE_Discharge_B1 1023 "Null" ;
VAL_ 2333798055 M2P_SOE_Charge_B1 1023 "Null" ;
VAL_ 2333798055 M2P_SOE_Discharge_B1 1023 "Null" ;
VAL_ 2333798056 M2P_SOE_Charge_B1 1023 "Null" ;
VAL_ 2333798056 M2P_SOE_Discharge_B1 1023 "Null" ;
VAL_ 2333798057 M2P_SOE_Charge_B1 1023 "Null" ;
VAL_ 2333798057 M2P_SOE_Discharge_B1 1023 "Null" ;
VAL_ 2333798058 M2P_SOE_Charge_B1 1023 "Null" ;
VAL_ 2333798058 M2P_SOE_Discharge_B1 1023 "Null" ;
VAL_ 2333798059 M2P_SOE_Charge_B1 1023 "Null" ;
VAL_ 2333798059 M2P_SOE_Discharge_B1 1023 "Null" ;
VAL_ 2333798060 M2P_SOE_Charge_B1 1023 "Null" ;
VAL_ 2333798060 M2P_SOE_Discharge_B1 1023 "Null" ;
VAL_ 2333798061 M2P_SOE_Charge_B1 1023 "Null" ;
VAL_ 2333798061 M2P_SOE_Discharge_B1 1023 "Null" ;
VAL_ 2333798062 M2P_SOE_Charge_B1 1023 "Null" ;
VAL_ 2333798062 M2P_SOE_Discharge_B1 1023 "Null" ;
VAL_ 2333798063 M2P_SOE_Charge_B1 1023 "Null" ;
VAL_ 2333798063 M2P_SOE_Discharge_B1 1023 "Null" ;
VAL_ 2333863569 M2P_Measure_Vol_B2_01 65535 "Invalid" ;
VAL_ 2333863569 M2P_Current_B2_01 65535 "Invalid" ;
VAL_ 2333863569 M2P_PermitMaxCharge_I_B2_01 65535 "Invalid" ;
VAL_ 2333863569 M2P_PermitMaxDisCharge_I_B2_01 65535 "Invalid" ;
VAL_ 2333863570 M2P_Measure_Vol_B2_02 65535 "Invalid" ;
VAL_ 2333863570 M2P_Current_B2_02 65535 "Invalid" ;
VAL_ 2333863570 M2P_PermitMaxCharge_I_B2_02 65535 "Invalid" ;
VAL_ 2333863570 M2P_PermitMaxDisCharge_I_B2_02 65535 "Invalid" ;
VAL_ 2333863571 M2P_Measure_Vol_B2_03 65535 "Invalid" ;
VAL_ 2333863571 M2P_Current_B2_03 65535 "Invalid" ;
VAL_ 2333863571 M2P_PermitMaxCharge_I_B2_03 65535 "Invalid" ;
VAL_ 2333863571 M2P_PermitMaxDisCharge_I_B2_03 65535 "Invalid" ;
VAL_ 2333863572 M2P_Measure_Vol_B2_04 65535 "Invalid" ;
VAL_ 2333863572 M2P_Current_B2_04 65535 "Invalid" ;
VAL_ 2333863572 M2P_PermitMaxCharge_I_B2_04 65535 "Invalid" ;
VAL_ 2333863572 M2P_PermitMaxDisCharge_I_B2_04 65535 "Invalid" ;
VAL_ 2333863573 M2P_Measure_Vol_B2_05 65535 "Invalid" ;
VAL_ 2333863573 M2P_Current_B2_05 65535 "Invalid" ;
VAL_ 2333863573 M2P_PermitMaxCharge_I_B2_05 65535 "Invalid" ;
VAL_ 2333863573 M2P_PermitMaxDisCharge_I_B2_05 65535 "Invalid" ;
VAL_ 2333863574 M2P_Measure_Vol_B2_06 65535 "Invalid" ;
VAL_ 2333863574 M2P_Current_B2_06 65535 "Invalid" ;
VAL_ 2333863574 M2P_PermitMaxCharge_I_B2_06 65535 "Invalid" ;
VAL_ 2333863574 M2P_PermitMaxDisCharge_I_B2_06 65535 "Invalid" ;
VAL_ 2333863575 M2P_Measure_Vol_B2_07 65535 "Invalid" ;
VAL_ 2333863575 M2P_Current_B2_07 65535 "Invalid" ;
VAL_ 2333863575 M2P_PermitMaxCharge_I_B2_07 65535 "Invalid" ;
VAL_ 2333863575 M2P_PermitMaxDisCharge_I_B2_07 65535 "Invalid" ;
VAL_ 2333863576 M2P_Measure_Vol_B2_08 65535 "Invalid" ;
VAL_ 2333863576 M2P_Current_B2_08 65535 "Invalid" ;
VAL_ 2333863576 M2P_PermitMaxCharge_I_B2_08 65535 "Invalid" ;
VAL_ 2333863576 M2P_PermitMaxDisCharge_I_B2_08 65535 "Invalid" ;
VAL_ 2333863577 M2P_Measure_Vol_B2_09 65535 "Invalid" ;
VAL_ 2333863577 M2P_Current_B2_09 65535 "Invalid" ;
VAL_ 2333863577 M2P_PermitMaxCharge_I_B2_09 65535 "Invalid" ;
VAL_ 2333863577 M2P_PermitMaxDisCharge_I_B2_09 65535 "Invalid" ;
VAL_ 2333863578 M2P_Measure_Vol_B2_10 65535 "Invalid" ;
VAL_ 2333863578 M2P_Current_B2_10 65535 "Invalid" ;
VAL_ 2333863578 M2P_PermitMaxCharge_I_B2_10 65535 "Invalid" ;
VAL_ 2333863578 M2P_PermitMaxDisCharge_I_B2_10 65535 "Invalid" ;
VAL_ 2333863579 M2P_Measure_Vol_B2_11 65535 "Invalid" ;
VAL_ 2333863579 M2P_Current_B2_11 65535 "Invalid" ;
VAL_ 2333863579 M2P_PermitMaxCharge_I_B2_11 65535 "Invalid" ;
VAL_ 2333863579 M2P_PermitMaxDisCharge_I_B2_11 65535 "Invalid" ;
VAL_ 2333863580 M2P_Measure_Vol_B2_12 65535 "Invalid" ;
VAL_ 2333863580 M2P_Current_B2_12 65535 "Invalid" ;
VAL_ 2333863580 M2P_PermitMaxCharge_I_B2_12 65535 "Invalid" ;
VAL_ 2333863580 M2P_PermitMaxDisCharge_I_B2_12 65535 "Invalid" ;
VAL_ 2333863581 M2P_Measure_Vol_B2_13 65535 "Invalid" ;
VAL_ 2333863581 M2P_Current_B2_13 65535 "Invalid" ;
VAL_ 2333863581 M2P_PermitMaxCharge_I_B2_13 65535 "Invalid" ;
VAL_ 2333863581 M2P_PermitMaxDisCharge_I_B2_13 65535 "Invalid" ;
VAL_ 2333863582 M2P_Measure_Vol_B2_14 65535 "Invalid" ;
VAL_ 2333863582 M2P_Current_B2_14 65535 "Invalid" ;
VAL_ 2333863582 M2P_PermitMaxCharge_I_B2_14 65535 "Invalid" ;
VAL_ 2333863582 M2P_PermitMaxDisCharge_I_B2_14 65535 "Invalid" ;
VAL_ 2333863583 M2P_Measure_Vol_B2_15 65535 "Invalid" ;
VAL_ 2333863583 M2P_Current_B2_15 65535 "Invalid" ;
VAL_ 2333863583 M2P_PermitMaxCharge_I_B2_15 65535 "Invalid" ;
VAL_ 2333863583 M2P_PermitMaxDisCharge_I_B2_15 65535 "Invalid" ;
VAL_ 2333863584 M2P_Measure_Vol_B2_16 65535 "Invalid" ;
VAL_ 2333863584 M2P_Current_B2_16 65535 "Invalid" ;
VAL_ 2333863584 M2P_PermitMaxCharge_I_B2_16 65535 "Invalid" ;
VAL_ 2333863584 M2P_PermitMaxDisCharge_I_B2_16 65535 "Invalid" ;
VAL_ 2333863585 M2P_Measure_Vol_B2_17 65535 "Invalid" ;
VAL_ 2333863585 M2P_Current_B2_17 65535 "Invalid" ;
VAL_ 2333863585 M2P_PermitMaxCharge_I_B2_17 65535 "Invalid" ;
VAL_ 2333863585 M2P_PermitMaxDisCharge_I_B2_17 65535 "Invalid" ;
VAL_ 2333863586 M2P_Measure_Vol_B2_18 65535 "Invalid" ;
VAL_ 2333863586 M2P_Current_B2_18 65535 "Invalid" ;
VAL_ 2333863586 M2P_PermitMaxCharge_I_B2_18 65535 "Invalid" ;
VAL_ 2333863586 M2P_PermitMaxDisCharge_I_B2_18 65535 "Invalid" ;
VAL_ 2333863587 M2P_Measure_Vol_B2_19 65535 "Invalid" ;
VAL_ 2333863587 M2P_Current_B2_19 65535 "Invalid" ;
VAL_ 2333863587 M2P_PermitMaxCharge_I_B2_19 65535 "Invalid" ;
VAL_ 2333863587 M2P_PermitMaxDisCharge_I_B2_19 65535 "Invalid" ;
VAL_ 2333863588 M2P_Measure_Vol_B2_20 65535 "Invalid" ;
VAL_ 2333863588 M2P_Current_B2_20 65535 "Invalid" ;
VAL_ 2333863588 M2P_PermitMaxCharge_I_B2_20 65535 "Invalid" ;
VAL_ 2333863588 M2P_PermitMaxDisCharge_I_B2_20 65535 "Invalid" ;
VAL_ 2333863589 M2P_Measure_Vol_B2_21 65535 "Invalid" ;
VAL_ 2333863589 M2P_Current_B2_21 65535 "Invalid" ;
VAL_ 2333863589 M2P_PermitMaxCharge_I_B2_21 65535 "Invalid" ;
VAL_ 2333863589 M2P_PermitMaxDisCharge_I_B2_21 65535 "Invalid" ;
VAL_ 2333863590 M2P_Measure_Vol_B2_22 65535 "Invalid" ;
VAL_ 2333863590 M2P_Current_B2_22 65535 "Invalid" ;
VAL_ 2333863590 M2P_PermitMaxCharge_I_B2_22 65535 "Invalid" ;
VAL_ 2333863590 M2P_PermitMaxDisCharge_I_B2_22 65535 "Invalid" ;
VAL_ 2333863591 M2P_Measure_Vol_B2_23 65535 "Invalid" ;
VAL_ 2333863591 M2P_Current_B2_23 65535 "Invalid" ;
VAL_ 2333863591 M2P_PermitMaxCharge_I_B2_23 65535 "Invalid" ;
VAL_ 2333863591 M2P_PermitMaxDisCharge_I_B2_23 65535 "Invalid" ;
VAL_ 2333863592 M2P_Measure_Vol_B2_24 65535 "Invalid" ;
VAL_ 2333863592 M2P_Current_B2_24 65535 "Invalid" ;
VAL_ 2333863592 M2P_PermitMaxCharge_I_B2_24 65535 "Invalid" ;
VAL_ 2333863592 M2P_PermitMaxDisCharge_I_B2_24 65535 "Invalid" ;
VAL_ 2333863593 M2P_Measure_Vol_B2_25 65535 "Invalid" ;
VAL_ 2333863593 M2P_Current_B2_25 65535 "Invalid" ;
VAL_ 2333863593 M2P_PermitMaxCharge_I_B2_25 65535 "Invalid" ;
VAL_ 2333863593 M2P_PermitMaxDisCharge_I_B2_25 65535 "Invalid" ;
VAL_ 2333863594 M2P_Measure_Vol_B2_26 65535 "Invalid" ;
VAL_ 2333863594 M2P_Current_B2_26 65535 "Invalid" ;
VAL_ 2333863594 M2P_PermitMaxCharge_I_B2_26 65535 "Invalid" ;
VAL_ 2333863594 M2P_PermitMaxDisCharge_I_B2_26 65535 "Invalid" ;
VAL_ 2333863595 M2P_Measure_Vol_B2_27 65535 "Invalid" ;
VAL_ 2333863595 M2P_Current_B2_27 65535 "Invalid" ;
VAL_ 2333863595 M2P_PermitMaxCharge_I_B2_27 65535 "Invalid" ;
VAL_ 2333863595 M2P_PermitMaxDisCharge_I_B2_27 65535 "Invalid" ;
VAL_ 2333863596 M2P_Measure_Vol_B2_28 65535 "Invalid" ;
VAL_ 2333863596 M2P_Current_B2_28 65535 "Invalid" ;
VAL_ 2333863596 M2P_PermitMaxCharge_I_B2_28 65535 "Invalid" ;
VAL_ 2333863596 M2P_PermitMaxDisCharge_I_B2_28 65535 "Invalid" ;
VAL_ 2333863597 M2P_Measure_Vol_B2_29 65535 "Invalid" ;
VAL_ 2333863597 M2P_Current_B2_29 65535 "Invalid" ;
VAL_ 2333863597 M2P_PermitMaxCharge_I_B2_29 65535 "Invalid" ;
VAL_ 2333863597 M2P_PermitMaxDisCharge_I_B2_29 65535 "Invalid" ;
VAL_ 2333863598 M2P_Measure_Vol_B2_30 65535 "Invalid" ;
VAL_ 2333863598 M2P_Current_B2_30 65535 "Invalid" ;
VAL_ 2333863598 M2P_PermitMaxCharge_I_B2_30 65535 "Invalid" ;
VAL_ 2333863598 M2P_PermitMaxDisCharge_I_B2_30 65535 "Invalid" ;
VAL_ 2333863599 M2P_Measure_Vol_B2_31 65535 "Invalid" ;
VAL_ 2333863599 M2P_Current_B2_31 65535 "Invalid" ;
VAL_ 2333863599 M2P_PermitMaxCharge_I_B2_31 65535 "Invalid" ;
VAL_ 2333863599 M2P_PermitMaxDisCharge_I_B2_31 65535 "Invalid" ;
VAL_ 2333994641 M2P_SysremEngy_Chg_B2_01 65535 "Invalid" ;
VAL_ 2333994641 M2P_SysremEngy_DisChg_B2_01 65535 "Invalid" ;
VAL_ 2333994642 M2P_SysremEngy_Chg_B2_02 65535 "Invalid" ;
VAL_ 2333994642 M2P_SysremEngy_DisChg_B2_02 65535 "Invalid" ;
VAL_ 2333994643 M2P_SysremEngy_Chg_B2_03 65535 "Invalid" ;
VAL_ 2333994643 M2P_SysremEngy_DisChg_B2_03 65535 "Invalid" ;
VAL_ 2333994644 M2P_SysremEngy_Chg_B2_04 65535 "Invalid" ;
VAL_ 2333994644 M2P_SysremEngy_DisChg_B2_04 65535 "Invalid" ;
VAL_ 2333994645 M2P_SysremEngy_Chg_B2_05 65535 "Invalid" ;
VAL_ 2333994645 M2P_SysremEngy_DisChg_B2_05 65535 "Invalid" ;
VAL_ 2333994646 M2P_SysremEngy_Chg_B2_06 65535 "Invalid" ;
VAL_ 2333994646 M2P_SysremEngy_DisChg_B2_06 65535 "Invalid" ;
VAL_ 2333994647 M2P_SysremEngy_Chg_B2_07 65535 "Invalid" ;
VAL_ 2333994647 M2P_SysremEngy_DisChg_B2_07 65535 "Invalid" ;
VAL_ 2333994648 M2P_SysremEngy_Chg_B2_08 65535 "Invalid" ;
VAL_ 2333994648 M2P_SysremEngy_DisChg_B2_08 65535 "Invalid" ;
VAL_ 2333994649 M2P_SysremEngy_Chg_B2_09 65535 "Invalid" ;
VAL_ 2333994649 M2P_SysremEngy_DisChg_B2_09 65535 "Invalid" ;
VAL_ 2333994650 M2P_SysremEngy_Chg_B2_10 65535 "Invalid" ;
VAL_ 2333994650 M2P_SysremEngy_DisChg_B2_10 65535 "Invalid" ;
VAL_ 2333994651 M2P_SysremEngy_Chg_B2_11 65535 "Invalid" ;
VAL_ 2333994651 M2P_SysremEngy_DisChg_B2_11 65535 "Invalid" ;
VAL_ 2333994652 M2P_SysremEngy_Chg_B2_12 65535 "Invalid" ;
VAL_ 2333994652 M2P_SysremEngy_DisChg_B2_12 65535 "Invalid" ;
VAL_ 2333994653 M2P_SysremEngy_Chg_B2_13 65535 "Invalid" ;
VAL_ 2333994653 M2P_SysremEngy_DisChg_B2_13 65535 "Invalid" ;
VAL_ 2333994654 M2P_SysremEngy_Chg_B2_14 65535 "Invalid" ;
VAL_ 2333994654 M2P_SysremEngy_DisChg_B2_14 65535 "Invalid" ;
VAL_ 2333994655 M2P_SysremEngy_Chg_B2_15 65535 "Invalid" ;
VAL_ 2333994655 M2P_SysremEngy_DisChg_B2_15 65535 "Invalid" ;
VAL_ 2333994656 M2P_SysremEngy_Chg_B2_16 65535 "Invalid" ;
VAL_ 2333994656 M2P_SysremEngy_DisChg_B2_16 65535 "Invalid" ;
VAL_ 2333994657 M2P_SysremEngy_Chg_B2_17 65535 "Invalid" ;
VAL_ 2333994657 M2P_SysremEngy_DisChg_B2_17 65535 "Invalid" ;
VAL_ 2333994658 M2P_SysremEngy_Chg_B2_18 65535 "Invalid" ;
VAL_ 2333994658 M2P_SysremEngy_DisChg_B2_18 65535 "Invalid" ;
VAL_ 2333994659 M2P_SysremEngy_Chg_B2_19 65535 "Invalid" ;
VAL_ 2333994659 M2P_SysremEngy_DisChg_B2_19 65535 "Invalid" ;
VAL_ 2333994660 M2P_SysremEngy_Chg_B2_20 65535 "Invalid" ;
VAL_ 2333994660 M2P_SysremEngy_DisChg_B2_20 65535 "Invalid" ;
VAL_ 2333994661 M2P_SysremEngy_Chg_B2_21 65535 "Invalid" ;
VAL_ 2333994661 M2P_SysremEngy_DisChg_B2_21 65535 "Invalid" ;
VAL_ 2333994662 M2P_SysremEngy_Chg_B2_22 65535 "Invalid" ;
VAL_ 2333994662 M2P_SysremEngy_DisChg_B2_22 65535 "Invalid" ;
VAL_ 2333994663 M2P_SysremEngy_Chg_B2_23 65535 "Invalid" ;
VAL_ 2333994663 M2P_SysremEngy_DisChg_B2_23 65535 "Invalid" ;
VAL_ 2333994664 M2P_SysremEngy_Chg_B2_24 65535 "Invalid" ;
VAL_ 2333994664 M2P_SysremEngy_DisChg_B2_24 65535 "Invalid" ;
VAL_ 2333994665 M2P_SysremEngy_Chg_B2_25 65535 "Invalid" ;
VAL_ 2333994665 M2P_SysremEngy_DisChg_B2_25 65535 "Invalid" ;
VAL_ 2333994666 M2P_SysremEngy_Chg_B2_26 65535 "Invalid" ;
VAL_ 2333994666 M2P_SysremEngy_DisChg_B2_26 65535 "Invalid" ;
VAL_ 2333994667 M2P_SysremEngy_Chg_B2_27 65535 "Invalid" ;
VAL_ 2333994667 M2P_SysremEngy_DisChg_B2_27 65535 "Invalid" ;
VAL_ 2333994668 M2P_SysremEngy_Chg_B2_28 65535 "Invalid" ;
VAL_ 2333994668 M2P_SysremEngy_DisChg_B2_28 65535 "Invalid" ;
VAL_ 2333994669 M2P_SysremEngy_Chg_B2_29 65535 "Invalid" ;
VAL_ 2333994669 M2P_SysremEngy_DisChg_B2_29 65535 "Invalid" ;
VAL_ 2333994670 M2P_SysremEngy_Chg_B2_30 65535 "Invalid" ;
VAL_ 2333994670 M2P_SysremEngy_DisChg_B2_30 65535 "Invalid" ;
VAL_ 2333994671 M2P_SysremEngy_Chg_B2_31 65535 "Invalid" ;
VAL_ 2333994671 M2P_SysremEngy_DisChg_B2_31 65535 "Invalid" ;
VAL_ 2334060177 M2P_BMS_Status_B2 0 "初始化状态" 1 "非满充满放状态" 2 "满充状态" 3 "满放状态" ;
VAL_ 2334060177 M2P_SOC_B2 1023 "Null" ;
VAL_ 2334060177 M2P_SOH_B2 255 "Null" ;
VAL_ 2334060178 M2P_BMS_Status_B2 0 "初始化状态" 1 "非满充满放状态" 2 "满充状态" 3 "满放状态" ;
VAL_ 2334060178 M2P_SOC_B2 1023 "Null" ;
VAL_ 2334060178 M2P_SOH_B2 255 "Null" ;
VAL_ 2334060179 M2P_BMS_Status_B2 0 "初始化状态" 1 "非满充满放状态" 2 "满充状态" 3 "满放状态" ;
VAL_ 2334060179 M2P_SOC_B2 1023 "Null" ;
VAL_ 2334060179 M2P_SOH_B2 255 "Null" ;
VAL_ 2334060180 M2P_BMS_Status_B2 0 "初始化状态" 1 "非满充满放状态" 2 "满充状态" 3 "满放状态" ;
VAL_ 2334060180 M2P_SOC_B2 1023 "Null" ;
VAL_ 2334060180 M2P_SOH_B2 255 "Null" ;
VAL_ 2334060181 M2P_BMS_Status_B2 0 "初始化状态" 1 "非满充满放状态" 2 "满充状态" 3 "满放状态" ;
VAL_ 2334060181 M2P_SOC_B2 1023 "Null" ;
VAL_ 2334060181 M2P_SOH_B2 255 "Null" ;
VAL_ 2334060182 M2P_BMS_Status_B2 0 "初始化状态" 1 "非满充满放状态" 2 "满充状态" 3 "满放状态" ;
VAL_ 2334060182 M2P_SOC_B2 1023 "Null" ;
VAL_ 2334060182 M2P_SOH_B2 255 "Null" ;
VAL_ 2334060183 M2P_BMS_Status_B2 0 "初始化状态" 1 "非满充满放状态" 2 "满充状态" 3 "满放状态" ;
VAL_ 2334060183 M2P_SOC_B2 1023 "Null" ;
VAL_ 2334060183 M2P_SOH_B2 255 "Null" ;
VAL_ 2334060184 M2P_BMS_Status_B2 0 "初始化状态" 1 "非满充满放状态" 2 "满充状态" 3 "满放状态" ;
VAL_ 2334060184 M2P_SOC_B2 1023 "Null" ;
VAL_ 2334060184 M2P_SOH_B2 255 "Null" ;
VAL_ 2334060185 M2P_BMS_Status_B2 0 "初始化状态" 1 "非满充满放状态" 2 "满充状态" 3 "满放状态" ;
VAL_ 2334060185 M2P_SOC_B2 1023 "Null" ;
VAL_ 2334060185 M2P_SOH_B2 255 "Null" ;
VAL_ 2334060186 M2P_BMS_Status_B2 0 "初始化状态" 1 "非满充满放状态" 2 "满充状态" 3 "满放状态" ;
VAL_ 2334060186 M2P_SOC_B2 1023 "Null" ;
VAL_ 2334060186 M2P_SOH_B2 255 "Null" ;
VAL_ 2334060187 M2P_BMS_Status_B2 0 "初始化状态" 1 "非满充满放状态" 2 "满充状态" 3 "满放状态" ;
VAL_ 2334060187 M2P_SOC_B2 1023 "Null" ;
VAL_ 2334060187 M2P_SOH_B2 255 "Null" ;
VAL_ 2334060188 M2P_BMS_Status_B2 0 "初始化状态" 1 "非满充满放状态" 2 "满充状态" 3 "满放状态" ;
VAL_ 2334060188 M2P_SOC_B2 1023 "Null" ;
VAL_ 2334060188 M2P_SOH_B2 255 "Null" ;
VAL_ 2334060189 M2P_BMS_Status_B2 0 "初始化状态" 1 "非满充满放状态" 2 "满充状态" 3 "满放状态" ;
VAL_ 2334060189 M2P_SOC_B2 1023 "Null" ;
VAL_ 2334060189 M2P_SOH_B2 255 "Null" ;
VAL_ 2334060190 M2P_BMS_Status_B2 0 "初始化状态" 1 "非满充满放状态" 2 "满充状态" 3 "满放状态" ;
VAL_ 2334060190 M2P_SOC_B2 1023 "Null" ;
VAL_ 2334060190 M2P_SOH_B2 255 "Null" ;
VAL_ 2334060191 M2P_BMS_Status_B2 0 "初始化状态" 1 "非满充满放状态" 2 "满充状态" 3 "满放状态" ;
VAL_ 2334060191 M2P_SOC_B2 1023 "Null" ;
VAL_ 2334060191 M2P_SOH_B2 255 "Null" ;
VAL_ 2334060192 M2P_BMS_Status_B2 0 "初始化状态" 1 "非满充满放状态" 2 "满充状态" 3 "满放状态" ;
VAL_ 2334060192 M2P_SOC_B2 1023 "Null" ;
VAL_ 2334060192 M2P_SOH_B2 255 "Null" ;
VAL_ 2334060193 M2P_BMS_Status_B2 0 "初始化状态" 1 "非满充满放状态" 2 "满充状态" 3 "满放状态" ;
VAL_ 2334060193 M2P_SOC_B2 1023 "Null" ;
VAL_ 2334060193 M2P_SOH_B2 255 "Null" ;
VAL_ 2334060194 M2P_BMS_Status_B2 0 "初始化状态" 1 "非满充满放状态" 2 "满充状态" 3 "满放状态" ;
VAL_ 2334060194 M2P_SOC_B2 1023 "Null" ;
VAL_ 2334060194 M2P_SOH_B2 255 "Null" ;
VAL_ 2334060195 M2P_BMS_Status_B2 0 "初始化状态" 1 "非满充满放状态" 2 "满充状态" 3 "满放状态" ;
VAL_ 2334060195 M2P_SOC_B2 1023 "Null" ;
VAL_ 2334060195 M2P_SOH_B2 255 "Null" ;
VAL_ 2334060196 M2P_BMS_Status_B2 0 "初始化状态" 1 "非满充满放状态" 2 "满充状态" 3 "满放状态" ;
VAL_ 2334060196 M2P_SOC_B2 1023 "Null" ;
VAL_ 2334060196 M2P_SOH_B2 255 "Null" ;
VAL_ 2334060197 M2P_BMS_Status_B2 0 "初始化状态" 1 "非满充满放状态" 2 "满充状态" 3 "满放状态" ;
VAL_ 2334060197 M2P_SOC_B2 1023 "Null" ;
VAL_ 2334060197 M2P_SOH_B2 255 "Null" ;
VAL_ 2334060198 M2P_BMS_Status_B2 0 "初始化状态" 1 "非满充满放状态" 2 "满充状态" 3 "满放状态" ;
VAL_ 2334060198 M2P_SOC_B2 1023 "Null" ;
VAL_ 2334060198 M2P_SOH_B2 255 "Null" ;
VAL_ 2334060199 M2P_BMS_Status_B2 0 "初始化状态" 1 "非满充满放状态" 2 "满充状态" 3 "满放状态" ;
VAL_ 2334060199 M2P_SOC_B2 1023 "Null" ;
VAL_ 2334060199 M2P_SOH_B2 255 "Null" ;
VAL_ 2334060200 M2P_BMS_Status_B2 0 "初始化状态" 1 "非满充满放状态" 2 "满充状态" 3 "满放状态" ;
VAL_ 2334060200 M2P_SOC_B2 1023 "Null" ;
VAL_ 2334060200 M2P_SOH_B2 255 "Null" ;
VAL_ 2334060201 M2P_BMS_Status_B2 0 "初始化状态" 1 "非满充满放状态" 2 "满充状态" 3 "满放状态" ;
VAL_ 2334060201 M2P_SOC_B2 1023 "Null" ;
VAL_ 2334060201 M2P_SOH_B2 255 "Null" ;
VAL_ 2334060202 M2P_BMS_Status_B2 0 "初始化状态" 1 "非满充满放状态" 2 "满充状态" 3 "满放状态" ;
VAL_ 2334060202 M2P_SOC_B2 1023 "Null" ;
VAL_ 2334060202 M2P_SOH_B2 255 "Null" ;
VAL_ 2334060203 M2P_BMS_Status_B2 0 "初始化状态" 1 "非满充满放状态" 2 "满充状态" 3 "满放状态" ;
VAL_ 2334060203 M2P_SOC_B2 1023 "Null" ;
VAL_ 2334060203 M2P_SOH_B2 255 "Null" ;
VAL_ 2334060204 M2P_BMS_Status_B2 0 "初始化状态" 1 "非满充满放状态" 2 "满充状态" 3 "满放状态" ;
VAL_ 2334060204 M2P_SOC_B2 1023 "Null" ;
VAL_ 2334060204 M2P_SOH_B2 255 "Null" ;
VAL_ 2334060205 M2P_BMS_Status_B2 0 "初始化状态" 1 "非满充满放状态" 2 "满充状态" 3 "满放状态" ;
VAL_ 2334060205 M2P_SOC_B2 1023 "Null" ;
VAL_ 2334060205 M2P_SOH_B2 255 "Null" ;
VAL_ 2334060206 M2P_BMS_Status_B2 0 "初始化状态" 1 "非满充满放状态" 2 "满充状态" 3 "满放状态" ;
VAL_ 2334060206 M2P_SOC_B2 1023 "Null" ;
VAL_ 2334060206 M2P_SOH_B2 255 "Null" ;
VAL_ 2334060207 M2P_BMS_Status_B2 0 "初始化状态" 1 "非满充满放状态" 2 "满充状态" 3 "满放状态" ;
VAL_ 2334060207 M2P_SOC_B2 1023 "Null" ;
VAL_ 2334060207 M2P_SOH_B2 255 "Null" ;
VAL_ 2334125713 M2P_SOE_Charge_B2 1023 "Null" ;
VAL_ 2334125713 M2P_SOE_Discharge_B2 1023 "Null" ;
VAL_ 2334125714 M2P_SOE_Charge_B2 1023 "Null" ;
VAL_ 2334125714 M2P_SOE_Discharge_B2 1023 "Null" ;
VAL_ 2334125715 M2P_SOE_Charge_B2 1023 "Null" ;
VAL_ 2334125715 M2P_SOE_Discharge_B2 1023 "Null" ;
VAL_ 2334125716 M2P_SOE_Charge_B2 1023 "Null" ;
VAL_ 2334125716 M2P_SOE_Discharge_B2 1023 "Null" ;
VAL_ 2334125717 M2P_SOE_Charge_B2 1023 "Null" ;
VAL_ 2334125717 M2P_SOE_Discharge_B2 1023 "Null" ;
VAL_ 2334125718 M2P_SOE_Charge_B2 1023 "Null" ;
VAL_ 2334125718 M2P_SOE_Discharge_B2 1023 "Null" ;
VAL_ 2334125719 M2P_SOE_Charge_B2 1023 "Null" ;
VAL_ 2334125719 M2P_SOE_Discharge_B2 1023 "Null" ;
VAL_ 2334125720 M2P_SOE_Charge_B2 1023 "Null" ;
VAL_ 2334125720 M2P_SOE_Discharge_B2 1023 "Null" ;
VAL_ 2334125721 M2P_SOE_Charge_B2 1023 "Null" ;
VAL_ 2334125721 M2P_SOE_Discharge_B2 1023 "Null" ;
VAL_ 2334125722 M2P_SOE_Charge_B2 1023 "Null" ;
VAL_ 2334125722 M2P_SOE_Discharge_B2 1023 "Null" ;
VAL_ 2334125723 M2P_SOE_Charge_B2 1023 "Null" ;
VAL_ 2334125723 M2P_SOE_Discharge_B2 1023 "Null" ;
VAL_ 2334125724 M2P_SOE_Charge_B2 1023 "Null" ;
VAL_ 2334125724 M2P_SOE_Discharge_B2 1023 "Null" ;
VAL_ 2334125725 M2P_SOE_Charge_B2 1023 "Null" ;
VAL_ 2334125725 M2P_SOE_Discharge_B2 1023 "Null" ;
VAL_ 2334125726 M2P_SOE_Charge_B2 1023 "Null" ;
VAL_ 2334125726 M2P_SOE_Discharge_B2 1023 "Null" ;
VAL_ 2334125727 M2P_SOE_Charge_B2 1023 "Null" ;
VAL_ 2334125727 M2P_SOE_Discharge_B2 1023 "Null" ;
VAL_ 2334125728 M2P_SOE_Charge_B2 1023 "Null" ;
VAL_ 2334125728 M2P_SOE_Discharge_B2 1023 "Null" ;
VAL_ 2334125729 M2P_SOE_Charge_B2 1023 "Null" ;
VAL_ 2334125729 M2P_SOE_Discharge_B2 1023 "Null" ;
VAL_ 2334125730 M2P_SOE_Charge_B2 1023 "Null" ;
VAL_ 2334125730 M2P_SOE_Discharge_B2 1023 "Null" ;
VAL_ 2334125731 M2P_SOE_Charge_B2 1023 "Null" ;
VAL_ 2334125731 M2P_SOE_Discharge_B2 1023 "Null" ;
VAL_ 2334125732 M2P_SOE_Charge_B2 1023 "Null" ;
VAL_ 2334125732 M2P_SOE_Discharge_B2 1023 "Null" ;
VAL_ 2334125733 M2P_SOE_Charge_B2 1023 "Null" ;
VAL_ 2334125733 M2P_SOE_Discharge_B2 1023 "Null" ;
VAL_ 2334125734 M2P_SOE_Charge_B2 1023 "Null" ;
VAL_ 2334125734 M2P_SOE_Discharge_B2 1023 "Null" ;
VAL_ 2334125735 M2P_SOE_Charge_B2 1023 "Null" ;
VAL_ 2334125735 M2P_SOE_Discharge_B2 1023 "Null" ;
VAL_ 2334125736 M2P_SOE_Charge_B2 1023 "Null" ;
VAL_ 2334125736 M2P_SOE_Discharge_B2 1023 "Null" ;
VAL_ 2334125737 M2P_SOE_Charge_B2 1023 "Null" ;
VAL_ 2334125737 M2P_SOE_Discharge_B2 1023 "Null" ;
VAL_ 2334125738 M2P_SOE_Charge_B2 1023 "Null" ;
VAL_ 2334125738 M2P_SOE_Discharge_B2 1023 "Null" ;
VAL_ 2334125739 M2P_SOE_Charge_B2 1023 "Null" ;
VAL_ 2334125739 M2P_SOE_Discharge_B2 1023 "Null" ;
VAL_ 2334125740 M2P_SOE_Charge_B2 1023 "Null" ;
VAL_ 2334125740 M2P_SOE_Discharge_B2 1023 "Null" ;
VAL_ 2334125741 M2P_SOE_Charge_B2 1023 "Null" ;
VAL_ 2334125741 M2P_SOE_Discharge_B2 1023 "Null" ;
VAL_ 2334125742 M2P_SOE_Charge_B2 1023 "Null" ;
VAL_ 2334125742 M2P_SOE_Discharge_B2 1023 "Null" ;
VAL_ 2334125743 M2P_SOE_Charge_B2 1023 "Null" ;
VAL_ 2334125743 M2P_SOE_Discharge_B2 1023 "Null" ;
VERSION ""

NS_ :

BS_:

BU_: MBMU PC SBMU IMM ETH DCDC LEMS

BO_ 2334191249 M2P_SUMDATA25__01: 8 MBMU
 SG_ M2P_Measure_Vol_B3_01 : 0|16@1+ (0.1,0) [0|6553.5] "V"  PC,SBMU
 SG_ M2P_Current_B3_01 : 16|16@1+ (1,-20000) [-20000|45535] "A"  PC,SBMU
 SG_ M2P_PermitMaxCharge_I_B3_01 : 32|16@1+ (1,-20000) [-20000|45535] "A"  PC
 SG_ M2P_PermitMaxDisCharge_I_B3_01 : 48|16@1+ (1,-20000) [-20000|45535] "A"  PC

BO_ 2334191250 M2P_SUMDATA25__02: 8 MBMU
 SG_ M2P_Measure_Vol_B3_02 : 0|16@1+ (0.1,0) [0|6553.5] "V"  PC,SBMU
 SG_ M2P_Current_B3_02 : 16|16@1+ (1,-20000) [-20000|45535] "A"  PC,SBMU
 SG_ M2P_PermitMaxCharge_I_B3_02 : 32|16@1+ (1,-20000) [-20000|45535] "A"  PC
 SG_ M2P_PermitMaxDisCharge_I_B3_02 : 48|16@1+ (1,-20000) [-20000|45535] "A"  PC

BO_ 2334191251 M2P_SUMDATA25__03: 8 MBMU
 SG_ M2P_Measure_Vol_B3_03 : 0|16@1+ (0.1,0) [0|6553.5] "V"  PC,SBMU
 SG_ M2P_Current_B3_03 : 16|16@1+ (1,-20000) [-20000|45535] "A"  PC,SBMU
 SG_ M2P_PermitMaxCharge_I_B3_03 : 32|16@1+ (1,-20000) [-20000|45535] "A"  PC
 SG_ M2P_PermitMaxDisCharge_I_B3_03 : 48|16@1+ (1,-20000) [-20000|45535] "A"  PC

BO_ 2334191252 M2P_SUMDATA25__04: 8 MBMU
 SG_ M2P_Measure_Vol_B3_04 : 0|16@1+ (0.1,0) [0|6553.5] "V"  PC,SBMU
 SG_ M2P_Current_B3_04 : 16|16@1+ (1,-20000) [-20000|45535] "A"  PC,SBMU
 SG_ M2P_PermitMaxCharge_I_B3_04 : 32|16@1+ (1,-20000) [-20000|45535] "A"  PC
 SG_ M2P_PermitMaxDisCharge_I_B3_04 : 48|16@1+ (1,-20000) [-20000|45535] "A"  PC

BO_ 2334191253 M2P_SUMDATA25__05: 8 MBMU
 SG_ M2P_Measure_Vol_B3_05 : 0|16@1+ (0.1,0) [0|6553.5] "V"  PC,SBMU
 SG_ M2P_Current_B3_05 : 16|16@1+ (1,-20000) [-20000|45535] "A"  PC,SBMU
 SG_ M2P_PermitMaxCharge_I_B3_05 : 32|16@1+ (1,-20000) [-20000|45535] "A"  PC
 SG_ M2P_PermitMaxDisCharge_I_B3_05 : 48|16@1+ (1,-20000) [-20000|45535] "A"  PC

BO_ 2334191254 M2P_SUMDATA25__06: 8 MBMU
 SG_ M2P_Measure_Vol_B3_06 : 0|16@1+ (0.1,0) [0|6553.5] "V"  PC,SBMU
 SG_ M2P_Current_B3_06 : 16|16@1+ (1,-20000) [-20000|45535] "A"  PC,SBMU
 SG_ M2P_PermitMaxCharge_I_B3_06 : 32|16@1+ (1,-20000) [-20000|45535] "A"  PC
 SG_ M2P_PermitMaxDisCharge_I_B3_06 : 48|16@1+ (1,-20000) [-20000|45535] "A"  PC

BO_ 2334191255 M2P_SUMDATA25__07: 8 MBMU
 SG_ M2P_Measure_Vol_B3_07 : 0|16@1+ (0.1,0) [0|6553.5] "V"  PC,SBMU
 SG_ M2P_Current_B3_07 : 16|16@1+ (1,-20000) [-20000|45535] "A"  PC,SBMU
 SG_ M2P_PermitMaxCharge_I_B3_07 : 32|16@1+ (1,-20000) [-20000|45535] "A"  PC
 SG_ M2P_PermitMaxDisCharge_I_B3_07 : 48|16@1+ (1,-20000) [-20000|45535] "A"  PC

BO_ 2334191256 M2P_SUMDATA25__08: 8 MBMU
 SG_ M2P_Measure_Vol_B3_08 : 0|16@1+ (0.1,0) [0|6553.5] "V"  PC,SBMU
 SG_ M2P_Current_B3_08 : 16|16@1+ (1,-20000) [-20000|45535] "A"  PC,SBMU
 SG_ M2P_PermitMaxCharge_I_B3_08 : 32|16@1+ (1,-20000) [-20000|45535] "A"  PC
 SG_ M2P_PermitMaxDisCharge_I_B3_08 : 48|16@1+ (1,-20000) [-20000|45535] "A"  PC

BO_ 2334191257 M2P_SUMDATA25__09: 8 MBMU
 SG_ M2P_Measure_Vol_B3_09 : 0|16@1+ (0.1,0) [0|6553.5] "V"  PC,SBMU
 SG_ M2P_Current_B3_09 : 16|16@1+ (1,-20000) [-20000|45535] "A"  PC,SBMU
 SG_ M2P_PermitMaxCharge_I_B3_09 : 32|16@1+ (1,-20000) [-20000|45535] "A"  PC
 SG_ M2P_PermitMaxDisCharge_I_B3_09 : 48|16@1+ (1,-20000) [-20000|45535] "A"  PC

BO_ 2334191258 M2P_SUMDATA25__10: 8 MBMU
 SG_ M2P_Measure_Vol_B3_10 : 0|16@1+ (0.1,0) [0|6553.5] "V"  PC,SBMU
 SG_ M2P_Current_B3_10 : 16|16@1+ (1,-20000) [-20000|45535] "A"  PC,SBMU
 SG_ M2P_PermitMaxCharge_I_B3_10 : 32|16@1+ (1,-20000) [-20000|45535] "A"  PC
 SG_ M2P_PermitMaxDisCharge_I_B3_10 : 48|16@1+ (1,-20000) [-20000|45535] "A"  PC

BO_ 2334191259 M2P_SUMDATA25__11: 8 MBMU
 SG_ M2P_Measure_Vol_B3_11 : 0|16@1+ (0.1,0) [0|6553.5] "V"  PC,SBMU
 SG_ M2P_Current_B3_11 : 16|16@1+ (1,-20000) [-20000|45535] "A"  PC,SBMU
 SG_ M2P_PermitMaxCharge_I_B3_11 : 32|16@1+ (1,-20000) [-20000|45535] "A"  PC
 SG_ M2P_PermitMaxDisCharge_I_B3_11 : 48|16@1+ (1,-20000) [-20000|45535] "A"  PC

BO_ 2334191260 M2P_SUMDATA25__12: 8 MBMU
 SG_ M2P_Measure_Vol_B3_12 : 0|16@1+ (0.1,0) [0|6553.5] "V"  PC,SBMU
 SG_ M2P_Current_B3_12 : 16|16@1+ (1,-20000) [-20000|45535] "A"  PC,SBMU
 SG_ M2P_PermitMaxCharge_I_B3_12 : 32|16@1+ (1,-20000) [-20000|45535] "A"  PC
 SG_ M2P_PermitMaxDisCharge_I_B3_12 : 48|16@1+ (1,-20000) [-20000|45535] "A"  PC

BO_ 2334191261 M2P_SUMDATA25__13: 8 MBMU
 SG_ M2P_Measure_Vol_B3_13 : 0|16@1+ (0.1,0) [0|6553.5] "V"  PC,SBMU
 SG_ M2P_Current_B3_13 : 16|16@1+ (1,-20000) [-20000|45535] "A"  PC,SBMU
 SG_ M2P_PermitMaxCharge_I_B3_13 : 32|16@1+ (1,-20000) [-20000|45535] "A"  PC
 SG_ M2P_PermitMaxDisCharge_I_B3_13 : 48|16@1+ (1,-20000) [-20000|45535] "A"  PC

BO_ 2334191262 M2P_SUMDATA25__14: 8 MBMU
 SG_ M2P_Measure_Vol_B3_14 : 0|16@1+ (0.1,0) [0|6553.5] "V"  PC,SBMU
 SG_ M2P_Current_B3_14 : 16|16@1+ (1,-20000) [-20000|45535] "A"  PC,SBMU
 SG_ M2P_PermitMaxCharge_I_B3_14 : 32|16@1+ (1,-20000) [-20000|45535] "A"  PC
 SG_ M2P_PermitMaxDisCharge_I_B3_14 : 48|16@1+ (1,-20000) [-20000|45535] "A"  PC

BO_ 2334191263 M2P_SUMDATA25__15: 8 MBMU
 SG_ M2P_Measure_Vol_B3_15 : 0|16@1+ (0.1,0) [0|6553.5] "V"  PC,SBMU
 SG_ M2P_Current_B3_15 : 16|16@1+ (1,-20000) [-20000|45535] "A"  PC,SBMU
 SG_ M2P_PermitMaxCharge_I_B3_15 : 32|16@1+ (1,-20000) [-20000|45535] "A"  PC
 SG_ M2P_PermitMaxDisCharge_I_B3_15 : 48|16@1+ (1,-20000) [-20000|45535] "A"  PC

BO_ 2334191264 M2P_SUMDATA25__16: 8 MBMU
 SG_ M2P_Measure_Vol_B3_16 : 0|16@1+ (0.1,0) [0|6553.5] "V"  PC,SBMU
 SG_ M2P_Current_B3_16 : 16|16@1+ (1,-20000) [-20000|45535] "A"  PC,SBMU
 SG_ M2P_PermitMaxCharge_I_B3_16 : 32|16@1+ (1,-20000) [-20000|45535] "A"  PC
 SG_ M2P_PermitMaxDisCharge_I_B3_16 : 48|16@1+ (1,-20000) [-20000|45535] "A"  PC

BO_ 2334191265 M2P_SUMDATA25__17: 8 MBMU
 SG_ M2P_Measure_Vol_B3_17 : 0|16@1+ (0.1,0) [0|6553.5] "V"  PC,SBMU
 SG_ M2P_Current_B3_17 : 16|16@1+ (1,-20000) [-20000|45535] "A"  PC,SBMU
 SG_ M2P_PermitMaxCharge_I_B3_17 : 32|16@1+ (1,-20000) [-20000|45535] "A"  PC
 SG_ M2P_PermitMaxDisCharge_I_B3_17 : 48|16@1+ (1,-20000) [-20000|45535] "A"  PC

BO_ 2334191266 M2P_SUMDATA25__18: 8 MBMU
 SG_ M2P_Measure_Vol_B3_18 : 0|16@1+ (0.1,0) [0|6553.5] "V"  PC,SBMU
 SG_ M2P_Current_B3_18 : 16|16@1+ (1,-20000) [-20000|45535] "A"  PC,SBMU
 SG_ M2P_PermitMaxCharge_I_B3_18 : 32|16@1+ (1,-20000) [-20000|45535] "A"  PC
 SG_ M2P_PermitMaxDisCharge_I_B3_18 : 48|16@1+ (1,-20000) [-20000|45535] "A"  PC

BO_ 2334191267 M2P_SUMDATA25__19: 8 MBMU
 SG_ M2P_Measure_Vol_B3_19 : 0|16@1+ (0.1,0) [0|6553.5] "V"  PC,SBMU
 SG_ M2P_Current_B3_19 : 16|16@1+ (1,-20000) [-20000|45535] "A"  PC,SBMU
 SG_ M2P_PermitMaxCharge_I_B3_19 : 32|16@1+ (1,-20000) [-20000|45535] "A"  PC
 SG_ M2P_PermitMaxDisCharge_I_B3_19 : 48|16@1+ (1,-20000) [-20000|45535] "A"  PC

BO_ 2334191268 M2P_SUMDATA25__20: 8 MBMU
 SG_ M2P_Measure_Vol_B3_20 : 0|16@1+ (0.1,0) [0|6553.5] "V"  PC,SBMU
 SG_ M2P_Current_B3_20 : 16|16@1+ (1,-20000) [-20000|45535] "A"  PC,SBMU
 SG_ M2P_PermitMaxCharge_I_B3_20 : 32|16@1+ (1,-20000) [-20000|45535] "A"  PC
 SG_ M2P_PermitMaxDisCharge_I_B3_20 : 48|16@1+ (1,-20000) [-20000|45535] "A"  PC

BO_ 2334191269 M2P_SUMDATA25__21: 8 MBMU
 SG_ M2P_Measure_Vol_B3_21 : 0|16@1+ (0.1,0) [0|6553.5] "V"  PC,SBMU
 SG_ M2P_Current_B3_21 : 16|16@1+ (1,-20000) [-20000|45535] "A"  PC,SBMU
 SG_ M2P_PermitMaxCharge_I_B3_21 : 32|16@1+ (1,-20000) [-20000|45535] "A"  PC
 SG_ M2P_PermitMaxDisCharge_I_B3_21 : 48|16@1+ (1,-20000) [-20000|45535] "A"  PC

BO_ 2334191270 M2P_SUMDATA25__22: 8 MBMU
 SG_ M2P_Measure_Vol_B3_22 : 0|16@1+ (0.1,0) [0|6553.5] "V"  PC,SBMU
 SG_ M2P_Current_B3_22 : 16|16@1+ (1,-20000) [-20000|45535] "A"  PC,SBMU
 SG_ M2P_PermitMaxCharge_I_B3_22 : 32|16@1+ (1,-20000) [-20000|45535] "A"  PC
 SG_ M2P_PermitMaxDisCharge_I_B3_22 : 48|16@1+ (1,-20000) [-20000|45535] "A"  PC

BO_ 2334191271 M2P_SUMDATA25__23: 8 MBMU
 SG_ M2P_Measure_Vol_B3_23 : 0|16@1+ (0.1,0) [0|6553.5] "V"  PC,SBMU
 SG_ M2P_Current_B3_23 : 16|16@1+ (1,-20000) [-20000|45535] "A"  PC,SBMU
 SG_ M2P_PermitMaxCharge_I_B3_23 : 32|16@1+ (1,-20000) [-20000|45535] "A"  PC
 SG_ M2P_PermitMaxDisCharge_I_B3_23 : 48|16@1+ (1,-20000) [-20000|45535] "A"  PC

BO_ 2334191272 M2P_SUMDATA25__24: 8 MBMU
 SG_ M2P_Measure_Vol_B3_24 : 0|16@1+ (0.1,0) [0|6553.5] "V"  PC,SBMU
 SG_ M2P_Current_B3_24 : 16|16@1+ (1,-20000) [-20000|45535] "A"  PC,SBMU
 SG_ M2P_PermitMaxCharge_I_B3_24 : 32|16@1+ (1,-20000) [-20000|45535] "A"  PC
 SG_ M2P_PermitMaxDisCharge_I_B3_24 : 48|16@1+ (1,-20000) [-20000|45535] "A"  PC

BO_ 2334191273 M2P_SUMDATA25__25: 8 MBMU
 SG_ M2P_Measure_Vol_B3_25 : 0|16@1+ (0.1,0) [0|6553.5] "V"  PC,SBMU
 SG_ M2P_Current_B3_25 : 16|16@1+ (1,-20000) [-20000|45535] "A"  PC,SBMU
 SG_ M2P_PermitMaxCharge_I_B3_25 : 32|16@1+ (1,-20000) [-20000|45535] "A"  PC
 SG_ M2P_PermitMaxDisCharge_I_B3_25 : 48|16@1+ (1,-20000) [-20000|45535] "A"  PC

BO_ 2334191274 M2P_SUMDATA25__26: 8 MBMU
 SG_ M2P_Measure_Vol_B3_26 : 0|16@1+ (0.1,0) [0|6553.5] "V"  PC,SBMU
 SG_ M2P_Current_B3_26 : 16|16@1+ (1,-20000) [-20000|45535] "A"  PC,SBMU
 SG_ M2P_PermitMaxCharge_I_B3_26 : 32|16@1+ (1,-20000) [-20000|45535] "A"  PC
 SG_ M2P_PermitMaxDisCharge_I_B3_26 : 48|16@1+ (1,-20000) [-20000|45535] "A"  PC

BO_ 2334191275 M2P_SUMDATA25__27: 8 MBMU
 SG_ M2P_Measure_Vol_B3_27 : 0|16@1+ (0.1,0) [0|6553.5] "V"  PC,SBMU
 SG_ M2P_Current_B3_27 : 16|16@1+ (1,-20000) [-20000|45535] "A"  PC,SBMU
 SG_ M2P_PermitMaxCharge_I_B3_27 : 32|16@1+ (1,-20000) [-20000|45535] "A"  PC
 SG_ M2P_PermitMaxDisCharge_I_B3_27 : 48|16@1+ (1,-20000) [-20000|45535] "A"  PC

BO_ 2334191276 M2P_SUMDATA25__28: 8 MBMU
 SG_ M2P_Measure_Vol_B3_28 : 0|16@1+ (0.1,0) [0|6553.5] "V"  PC,SBMU
 SG_ M2P_Current_B3_28 : 16|16@1+ (1,-20000) [-20000|45535] "A"  PC,SBMU
 SG_ M2P_PermitMaxCharge_I_B3_28 : 32|16@1+ (1,-20000) [-20000|45535] "A"  PC
 SG_ M2P_PermitMaxDisCharge_I_B3_28 : 48|16@1+ (1,-20000) [-20000|45535] "A"  PC

BO_ 2334191277 M2P_SUMDATA25__29: 8 MBMU
 SG_ M2P_Measure_Vol_B3_29 : 0|16@1+ (0.1,0) [0|6553.5] "V"  PC,SBMU
 SG_ M2P_Current_B3_29 : 16|16@1+ (1,-20000) [-20000|45535] "A"  PC,SBMU
 SG_ M2P_PermitMaxCharge_I_B3_29 : 32|16@1+ (1,-20000) [-20000|45535] "A"  PC
 SG_ M2P_PermitMaxDisCharge_I_B3_29 : 48|16@1+ (1,-20000) [-20000|45535] "A"  PC

BO_ 2334191278 M2P_SUMDATA25__30: 8 MBMU
 SG_ M2P_Measure_Vol_B3_30 : 0|16@1+ (0.1,0) [0|6553.5] "V"  PC,SBMU
 SG_ M2P_Current_B3_30 : 16|16@1+ (1,-20000) [-20000|45535] "A"  PC,SBMU
 SG_ M2P_PermitMaxCharge_I_B3_30 : 32|16@1+ (1,-20000) [-20000|45535] "A"  PC
 SG_ M2P_PermitMaxDisCharge_I_B3_30 : 48|16@1+ (1,-20000) [-20000|45535] "A"  PC

BO_ 2334191279 M2P_SUMDATA25__31: 8 MBMU
 SG_ M2P_Measure_Vol_B3_31 : 0|16@1+ (0.1,0) [0|6553.5] "V"  PC,SBMU
 SG_ M2P_Current_B3_31 : 16|16@1+ (1,-20000) [-20000|45535] "A"  PC,SBMU
 SG_ M2P_PermitMaxCharge_I_B3_31 : 32|16@1+ (1,-20000) [-20000|45535] "A"  PC
 SG_ M2P_PermitMaxDisCharge_I_B3_31 : 48|16@1+ (1,-20000) [-20000|45535] "A"  PC

BO_ 2334256785 M2P_SUMDATA26__01: 8 MBMU
 SG_ M2P_PermitMaxVolt_B3_01 : 0|16@1+ (0.1,0) [0|6553.5] "V"  PC
 SG_ M2P_PermitMinVolt_B3_01 : 16|16@1+ (0.1,0) [0|6553.5] "V"  PC
 SG_ M2P_PermitMaxPow_Chg_B3_01 : 32|16@1+ (1,-20000) [-20000|45535] "Kw"  PC
 SG_ M2P_PermitMaxPow_DisChg_B3_01 : 48|16@1+ (1,-20000) [-20000|45535] "Kw"  PC

BO_ 2334256786 M2P_SUMDATA26__02: 8 MBMU
 SG_ M2P_PermitMaxVolt_B3_02 : 0|16@1+ (0.1,0) [0|6553.5] "V"  PC
 SG_ M2P_PermitMinVolt_B3_02 : 16|16@1+ (0.1,0) [0|6553.5] "V"  PC
 SG_ M2P_PermitMaxPow_Chg_B3_02 : 32|16@1+ (1,-20000) [-20000|45535] "Kw"  PC
 SG_ M2P_PermitMaxPow_DisChg_B3_02 : 48|16@1+ (1,-20000) [-20000|45535] "Kw"  PC

BO_ 2334256787 M2P_SUMDATA26__03: 8 MBMU
 SG_ M2P_PermitMaxVolt_B3_03 : 0|16@1+ (0.1,0) [0|6553.5] "V"  PC
 SG_ M2P_PermitMinVolt_B3_03 : 16|16@1+ (0.1,0) [0|6553.5] "V"  PC
 SG_ M2P_PermitMaxPow_Chg_B3_03 : 32|16@1+ (1,-20000) [-20000|45535] "Kw"  PC
 SG_ M2P_PermitMaxPow_DisChg_B3_03 : 48|16@1+ (1,-20000) [-20000|45535] "Kw"  PC

BO_ 2334256788 M2P_SUMDATA26__04: 8 MBMU
 SG_ M2P_PermitMaxVolt_B3_04 : 0|16@1+ (0.1,0) [0|6553.5] "V"  PC
 SG_ M2P_PermitMinVolt_B3_04 : 16|16@1+ (0.1,0) [0|6553.5] "V"  PC
 SG_ M2P_PermitMaxPow_Chg_B3_04 : 32|16@1+ (1,-20000) [-20000|45535] "Kw"  PC
 SG_ M2P_PermitMaxPow_DisChg_B3_04 : 48|16@1+ (1,-20000) [-20000|45535] "Kw"  PC

BO_ 2334256789 M2P_SUMDATA26__05: 8 MBMU
 SG_ M2P_PermitMaxVolt_B3_05 : 0|16@1+ (0.1,0) [0|6553.5] "V"  PC
 SG_ M2P_PermitMinVolt_B3_05 : 16|16@1+ (0.1,0) [0|6553.5] "V"  PC
 SG_ M2P_PermitMaxPow_Chg_B3_05 : 32|16@1+ (1,-20000) [-20000|45535] "Kw"  PC
 SG_ M2P_PermitMaxPow_DisChg_B3_05 : 48|16@1+ (1,-20000) [-20000|45535] "Kw"  PC

BO_ 2334256790 M2P_SUMDATA26__06: 8 MBMU
 SG_ M2P_PermitMaxVolt_B3_06 : 0|16@1+ (0.1,0) [0|6553.5] "V"  PC
 SG_ M2P_PermitMinVolt_B3_06 : 16|16@1+ (0.1,0) [0|6553.5] "V"  PC
 SG_ M2P_PermitMaxPow_Chg_B3_06 : 32|16@1+ (1,-20000) [-20000|45535] "Kw"  PC
 SG_ M2P_PermitMaxPow_DisChg_B3_06 : 48|16@1+ (1,-20000) [-20000|45535] "Kw"  PC

BO_ 2334256791 M2P_SUMDATA26__07: 8 MBMU
 SG_ M2P_PermitMaxVolt_B3_07 : 0|16@1+ (0.1,0) [0|6553.5] "V"  PC
 SG_ M2P_PermitMinVolt_B3_07 : 16|16@1+ (0.1,0) [0|6553.5] "V"  PC
 SG_ M2P_PermitMaxPow_Chg_B3_07 : 32|16@1+ (1,-20000) [-20000|45535] "Kw"  PC
 SG_ M2P_PermitMaxPow_DisChg_B3_07 : 48|16@1+ (1,-20000) [-20000|45535] "Kw"  PC

BO_ 2334256792 M2P_SUMDATA26__08: 8 MBMU
 SG_ M2P_PermitMaxVolt_B3_08 : 0|16@1+ (0.1,0) [0|6553.5] "V"  PC
 SG_ M2P_PermitMinVolt_B3_08 : 16|16@1+ (0.1,0) [0|6553.5] "V"  PC
 SG_ M2P_PermitMaxPow_Chg_B3_08 : 32|16@1+ (1,-20000) [-20000|45535] "Kw"  PC
 SG_ M2P_PermitMaxPow_DisChg_B3_08 : 48|16@1+ (1,-20000) [-20000|45535] "Kw"  PC

BO_ 2334256793 M2P_SUMDATA26__09: 8 MBMU
 SG_ M2P_PermitMaxVolt_B3_09 : 0|16@1+ (0.1,0) [0|6553.5] "V"  PC
 SG_ M2P_PermitMinVolt_B3_09 : 16|16@1+ (0.1,0) [0|6553.5] "V"  PC
 SG_ M2P_PermitMaxPow_Chg_B3_09 : 32|16@1+ (1,-20000) [-20000|45535] "Kw"  PC
 SG_ M2P_PermitMaxPow_DisChg_B3_09 : 48|16@1+ (1,-20000) [-20000|45535] "Kw"  PC

BO_ 2334256794 M2P_SUMDATA26__10: 8 MBMU
 SG_ M2P_PermitMaxVolt_B3_10 : 0|16@1+ (0.1,0) [0|6553.5] "V"  PC
 SG_ M2P_PermitMinVolt_B3_10 : 16|16@1+ (0.1,0) [0|6553.5] "V"  PC
 SG_ M2P_PermitMaxPow_Chg_B3_10 : 32|16@1+ (1,-20000) [-20000|45535] "Kw"  PC
 SG_ M2P_PermitMaxPow_DisChg_B3_10 : 48|16@1+ (1,-20000) [-20000|45535] "Kw"  PC

BO_ 2334256795 M2P_SUMDATA26__11: 8 MBMU
 SG_ M2P_PermitMaxVolt_B3_11 : 0|16@1+ (0.1,0) [0|6553.5] "V"  PC
 SG_ M2P_PermitMinVolt_B3_11 : 16|16@1+ (0.1,0) [0|6553.5] "V"  PC
 SG_ M2P_PermitMaxPow_Chg_B3_11 : 32|16@1+ (1,-20000) [-20000|45535] "Kw"  PC
 SG_ M2P_PermitMaxPow_DisChg_B3_11 : 48|16@1+ (1,-20000) [-20000|45535] "Kw"  PC

BO_ 2334256796 M2P_SUMDATA26__12: 8 MBMU
 SG_ M2P_PermitMaxVolt_B3_12 : 0|16@1+ (0.1,0) [0|6553.5] "V"  PC
 SG_ M2P_PermitMinVolt_B3_12 : 16|16@1+ (0.1,0) [0|6553.5] "V"  PC
 SG_ M2P_PermitMaxPow_Chg_B3_12 : 32|16@1+ (1,-20000) [-20000|45535] "Kw"  PC
 SG_ M2P_PermitMaxPow_DisChg_B3_12 : 48|16@1+ (1,-20000) [-20000|45535] "Kw"  PC

BO_ 2334256797 M2P_SUMDATA26__13: 8 MBMU
 SG_ M2P_PermitMaxVolt_B3_13 : 0|16@1+ (0.1,0) [0|6553.5] "V"  PC
 SG_ M2P_PermitMinVolt_B3_13 : 16|16@1+ (0.1,0) [0|6553.5] "V"  PC
 SG_ M2P_PermitMaxPow_Chg_B3_13 : 32|16@1+ (1,-20000) [-20000|45535] "Kw"  PC
 SG_ M2P_PermitMaxPow_DisChg_B3_13 : 48|16@1+ (1,-20000) [-20000|45535] "Kw"  PC

BO_ 2334256798 M2P_SUMDATA26__14: 8 MBMU
 SG_ M2P_PermitMaxVolt_B3_14 : 0|16@1+ (0.1,0) [0|6553.5] "V"  PC
 SG_ M2P_PermitMinVolt_B3_14 : 16|16@1+ (0.1,0) [0|6553.5] "V"  PC
 SG_ M2P_PermitMaxPow_Chg_B3_14 : 32|16@1+ (1,-20000) [-20000|45535] "Kw"  PC
 SG_ M2P_PermitMaxPow_DisChg_B3_14 : 48|16@1+ (1,-20000) [-20000|45535] "Kw"  PC

BO_ 2334256799 M2P_SUMDATA26__15: 8 MBMU
 SG_ M2P_PermitMaxVolt_B3_15 : 0|16@1+ (0.1,0) [0|6553.5] "V"  PC
 SG_ M2P_PermitMinVolt_B3_15 : 16|16@1+ (0.1,0) [0|6553.5] "V"  PC
 SG_ M2P_PermitMaxPow_Chg_B3_15 : 32|16@1+ (1,-20000) [-20000|45535] "Kw"  PC
 SG_ M2P_PermitMaxPow_DisChg_B3_15 : 48|16@1+ (1,-20000) [-20000|45535] "Kw"  PC

BO_ 2334256800 M2P_SUMDATA26__16: 8 MBMU
 SG_ M2P_PermitMaxVolt_B3_16 : 0|16@1+ (0.1,0) [0|6553.5] "V"  PC
 SG_ M2P_PermitMinVolt_B3_16 : 16|16@1+ (0.1,0) [0|6553.5] "V"  PC
 SG_ M2P_PermitMaxPow_Chg_B3_16 : 32|16@1+ (1,-20000) [-20000|45535] "Kw"  PC
 SG_ M2P_PermitMaxPow_DisChg_B3_16 : 48|16@1+ (1,-20000) [-20000|45535] "Kw"  PC

BO_ 2334256801 M2P_SUMDATA26__17: 8 MBMU
 SG_ M2P_PermitMaxVolt_B3_17 : 0|16@1+ (0.1,0) [0|6553.5] "V"  PC
 SG_ M2P_PermitMinVolt_B3_17 : 16|16@1+ (0.1,0) [0|6553.5] "V"  PC
 SG_ M2P_PermitMaxPow_Chg_B3_17 : 32|16@1+ (1,-20000) [-20000|45535] "Kw"  PC
 SG_ M2P_PermitMaxPow_DisChg_B3_17 : 48|16@1+ (1,-20000) [-20000|45535] "Kw"  PC

BO_ 2334256802 M2P_SUMDATA26__18: 8 MBMU
 SG_ M2P_PermitMaxVolt_B3_18 : 0|16@1+ (0.1,0) [0|6553.5] "V"  PC
 SG_ M2P_PermitMinVolt_B3_18 : 16|16@1+ (0.1,0) [0|6553.5] "V"  PC
 SG_ M2P_PermitMaxPow_Chg_B3_18 : 32|16@1+ (1,-20000) [-20000|45535] "Kw"  PC
 SG_ M2P_PermitMaxPow_DisChg_B3_18 : 48|16@1+ (1,-20000) [-20000|45535] "Kw"  PC

BO_ 2334256803 M2P_SUMDATA26__19: 8 MBMU
 SG_ M2P_PermitMaxVolt_B3_19 : 0|16@1+ (0.1,0) [0|6553.5] "V"  PC
 SG_ M2P_PermitMinVolt_B3_19 : 16|16@1+ (0.1,0) [0|6553.5] "V"  PC
 SG_ M2P_PermitMaxPow_Chg_B3_19 : 32|16@1+ (1,-20000) [-20000|45535] "Kw"  PC
 SG_ M2P_PermitMaxPow_DisChg_B3_19 : 48|16@1+ (1,-20000) [-20000|45535] "Kw"  PC

BO_ 2334256804 M2P_SUMDATA26__20: 8 MBMU
 SG_ M2P_PermitMaxVolt_B3_20 : 0|16@1+ (0.1,0) [0|6553.5] "V"  PC
 SG_ M2P_PermitMinVolt_B3_20 : 16|16@1+ (0.1,0) [0|6553.5] "V"  PC
 SG_ M2P_PermitMaxPow_Chg_B3_20 : 32|16@1+ (1,-20000) [-20000|45535] "Kw"  PC
 SG_ M2P_PermitMaxPow_DisChg_B3_20 : 48|16@1+ (1,-20000) [-20000|45535] "Kw"  PC

BO_ 2334256805 M2P_SUMDATA26__21: 8 MBMU
 SG_ M2P_PermitMaxVolt_B3_21 : 0|16@1+ (0.1,0) [0|6553.5] "V"  PC
 SG_ M2P_PermitMinVolt_B3_21 : 16|16@1+ (0.1,0) [0|6553.5] "V"  PC
 SG_ M2P_PermitMaxPow_Chg_B3_21 : 32|16@1+ (1,-20000) [-20000|45535] "Kw"  PC
 SG_ M2P_PermitMaxPow_DisChg_B3_21 : 48|16@1+ (1,-20000) [-20000|45535] "Kw"  PC

BO_ 2334256806 M2P_SUMDATA26__22: 8 MBMU
 SG_ M2P_PermitMaxVolt_B3_22 : 0|16@1+ (0.1,0) [0|6553.5] "V"  PC
 SG_ M2P_PermitMinVolt_B3_22 : 16|16@1+ (0.1,0) [0|6553.5] "V"  PC
 SG_ M2P_PermitMaxPow_Chg_B3_22 : 32|16@1+ (1,-20000) [-20000|45535] "Kw"  PC
 SG_ M2P_PermitMaxPow_DisChg_B3_22 : 48|16@1+ (1,-20000) [-20000|45535] "Kw"  PC

BO_ 2334256807 M2P_SUMDATA26__23: 8 MBMU
 SG_ M2P_PermitMaxVolt_B3_23 : 0|16@1+ (0.1,0) [0|6553.5] "V"  PC
 SG_ M2P_PermitMinVolt_B3_23 : 16|16@1+ (0.1,0) [0|6553.5] "V"  PC
 SG_ M2P_PermitMaxPow_Chg_B3_23 : 32|16@1+ (1,-20000) [-20000|45535] "Kw"  PC
 SG_ M2P_PermitMaxPow_DisChg_B3_23 : 48|16@1+ (1,-20000) [-20000|45535] "Kw"  PC

BO_ 2334256808 M2P_SUMDATA26__24: 8 MBMU
 SG_ M2P_PermitMaxVolt_B3_24 : 0|16@1+ (0.1,0) [0|6553.5] "V"  PC
 SG_ M2P_PermitMinVolt_B3_24 : 16|16@1+ (0.1,0) [0|6553.5] "V"  PC
 SG_ M2P_PermitMaxPow_Chg_B3_24 : 32|16@1+ (1,-20000) [-20000|45535] "Kw"  PC
 SG_ M2P_PermitMaxPow_DisChg_B3_24 : 48|16@1+ (1,-20000) [-20000|45535] "Kw"  PC

BO_ 2334256809 M2P_SUMDATA26__25: 8 MBMU
 SG_ M2P_PermitMaxVolt_B3_25 : 0|16@1+ (0.1,0) [0|6553.5] "V"  PC
 SG_ M2P_PermitMinVolt_B3_25 : 16|16@1+ (0.1,0) [0|6553.5] "V"  PC
 SG_ M2P_PermitMaxPow_Chg_B3_25 : 32|16@1+ (1,-20000) [-20000|45535] "Kw"  PC
 SG_ M2P_PermitMaxPow_DisChg_B3_25 : 48|16@1+ (1,-20000) [-20000|45535] "Kw"  PC

BO_ 2334256810 M2P_SUMDATA26__26: 8 MBMU
 SG_ M2P_PermitMaxVolt_B3_26 : 0|16@1+ (0.1,0) [0|6553.5] "V"  PC
 SG_ M2P_PermitMinVolt_B3_26 : 16|16@1+ (0.1,0) [0|6553.5] "V"  PC
 SG_ M2P_PermitMaxPow_Chg_B3_26 : 32|16@1+ (1,-20000) [-20000|45535] "Kw"  PC
 SG_ M2P_PermitMaxPow_DisChg_B3_26 : 48|16@1+ (1,-20000) [-20000|45535] "Kw"  PC

BO_ 2334256811 M2P_SUMDATA26__27: 8 MBMU
 SG_ M2P_PermitMaxVolt_B3_27 : 0|16@1+ (0.1,0) [0|6553.5] "V"  PC
 SG_ M2P_PermitMinVolt_B3_27 : 16|16@1+ (0.1,0) [0|6553.5] "V"  PC
 SG_ M2P_PermitMaxPow_Chg_B3_27 : 32|16@1+ (1,-20000) [-20000|45535] "Kw"  PC
 SG_ M2P_PermitMaxPow_DisChg_B3_27 : 48|16@1+ (1,-20000) [-20000|45535] "Kw"  PC

BO_ 2334256812 M2P_SUMDATA26__28: 8 MBMU
 SG_ M2P_PermitMaxVolt_B3_28 : 0|16@1+ (0.1,0) [0|6553.5] "V"  PC
 SG_ M2P_PermitMinVolt_B3_28 : 16|16@1+ (0.1,0) [0|6553.5] "V"  PC
 SG_ M2P_PermitMaxPow_Chg_B3_28 : 32|16@1+ (1,-20000) [-20000|45535] "Kw"  PC
 SG_ M2P_PermitMaxPow_DisChg_B3_28 : 48|16@1+ (1,-20000) [-20000|45535] "Kw"  PC

BO_ 2334256813 M2P_SUMDATA26__29: 8 MBMU
 SG_ M2P_PermitMaxVolt_B3_29 : 0|16@1+ (0.1,0) [0|6553.5] "V"  PC
 SG_ M2P_PermitMinVolt_B3_29 : 16|16@1+ (0.1,0) [0|6553.5] "V"  PC
 SG_ M2P_PermitMaxPow_Chg_B3_29 : 32|16@1+ (1,-20000) [-20000|45535] "Kw"  PC
 SG_ M2P_PermitMaxPow_DisChg_B3_29 : 48|16@1+ (1,-20000) [-20000|45535] "Kw"  PC

BO_ 2334256814 M2P_SUMDATA26__30: 8 MBMU
 SG_ M2P_PermitMaxVolt_B3_30 : 0|16@1+ (0.1,0) [0|6553.5] "V"  PC
 SG_ M2P_PermitMinVolt_B3_30 : 16|16@1+ (0.1,0) [0|6553.5] "V"  PC
 SG_ M2P_PermitMaxPow_Chg_B3_30 : 32|16@1+ (1,-20000) [-20000|45535] "Kw"  PC
 SG_ M2P_PermitMaxPow_DisChg_B3_30 : 48|16@1+ (1,-20000) [-20000|45535] "Kw"  PC

BO_ 2334256815 M2P_SUMDATA26__31: 8 MBMU
 SG_ M2P_PermitMaxVolt_B3_31 : 0|16@1+ (0.1,0) [0|6553.5] "V"  PC
 SG_ M2P_PermitMinVolt_B3_31 : 16|16@1+ (0.1,0) [0|6553.5] "V"  PC
 SG_ M2P_PermitMaxPow_Chg_B3_31 : 32|16@1+ (1,-20000) [-20000|45535] "Kw"  PC
 SG_ M2P_PermitMaxPow_DisChg_B3_31 : 48|16@1+ (1,-20000) [-20000|45535] "Kw"  PC

BO_ 2334322321 M2P_SUMDATA27__01: 8 MBMU
 SG_ M2P_Power_B3_01 : 0|16@1+ (1,-20000) [-20000|45535] "Kw"  PC
 SG_ M2P_SysremEngy_Chg_B3_01 : 16|16@1+ (1,0) [0|65535] "Kwh"  PC
 SG_ M2P_SysremEngy_DisChg_B3_01 : 32|16@1+ (1,0) [0|65535] "Kwh"  PC
 SG_ M2P_SysMaxVolt_B3_01 : 48|16@1+ (1,0) [0|65535] "mv"  PC

BO_ 2334322322 M2P_SUMDATA27__02: 8 MBMU
 SG_ M2P_Power_B3_02 : 0|16@1+ (1,-20000) [-20000|45535] "Kw"  PC
 SG_ M2P_SysremEngy_Chg_B3_02 : 16|16@1+ (1,0) [0|65535] "Kwh"  PC
 SG_ M2P_SysremEngy_DisChg_B3_02 : 32|16@1+ (1,0) [0|65535] "Kwh"  PC
 SG_ M2P_SysMaxVolt_B3_02 : 48|16@1+ (1,0) [0|65535] "mv"  PC

BO_ 2334322323 M2P_SUMDATA27__03: 8 MBMU
 SG_ M2P_Power_B3_03 : 0|16@1+ (1,-20000) [-20000|45535] "Kw"  PC
 SG_ M2P_SysremEngy_Chg_B3_03 : 16|16@1+ (1,0) [0|65535] "Kwh"  PC
 SG_ M2P_SysremEngy_DisChg_B3_03 : 32|16@1+ (1,0) [0|65535] "Kwh"  PC
 SG_ M2P_SysMaxVolt_B3_03 : 48|16@1+ (1,0) [0|65535] "mv"  PC

BO_ 2334322324 M2P_SUMDATA27__04: 8 MBMU
 SG_ M2P_Power_B3_04 : 0|16@1+ (1,-20000) [-20000|45535] "Kw"  PC
 SG_ M2P_SysremEngy_Chg_B3_04 : 16|16@1+ (1,0) [0|65535] "Kwh"  PC
 SG_ M2P_SysremEngy_DisChg_B3_04 : 32|16@1+ (1,0) [0|65535] "Kwh"  PC
 SG_ M2P_SysMaxVolt_B3_04 : 48|16@1+ (1,0) [0|65535] "mv"  PC

BO_ 2334322325 M2P_SUMDATA27__05: 8 MBMU
 SG_ M2P_Power_B3_05 : 0|16@1+ (1,-20000) [-20000|45535] "Kw"  PC
 SG_ M2P_SysremEngy_Chg_B3_05 : 16|16@1+ (1,0) [0|65535] "Kwh"  PC
 SG_ M2P_SysremEngy_DisChg_B3_05 : 32|16@1+ (1,0) [0|65535] "Kwh"  PC
 SG_ M2P_SysMaxVolt_B3_05 : 48|16@1+ (1,0) [0|65535] "mv"  PC

BO_ 2334322326 M2P_SUMDATA27__06: 8 MBMU
 SG_ M2P_Power_B3_06 : 0|16@1+ (1,-20000) [-20000|45535] "Kw"  PC
 SG_ M2P_SysremEngy_Chg_B3_06 : 16|16@1+ (1,0) [0|65535] "Kwh"  PC
 SG_ M2P_SysremEngy_DisChg_B3_06 : 32|16@1+ (1,0) [0|65535] "Kwh"  PC
 SG_ M2P_SysMaxVolt_B3_06 : 48|16@1+ (1,0) [0|65535] "mv"  PC

BO_ 2334322327 M2P_SUMDATA27__07: 8 MBMU
 SG_ M2P_Power_B3_07 : 0|16@1+ (1,-20000) [-20000|45535] "Kw"  PC
 SG_ M2P_SysremEngy_Chg_B3_07 : 16|16@1+ (1,0) [0|65535] "Kwh"  PC
 SG_ M2P_SysremEngy_DisChg_B3_07 : 32|16@1+ (1,0) [0|65535] "Kwh"  PC
 SG_ M2P_SysMaxVolt_B3_07 : 48|16@1+ (1,0) [0|65535] "mv"  PC

BO_ 2334322328 M2P_SUMDATA27__08: 8 MBMU
 SG_ M2P_Power_B3_08 : 0|16@1+ (1,-20000) [-20000|45535] "Kw"  PC
 SG_ M2P_SysremEngy_Chg_B3_08 : 16|16@1+ (1,0) [0|65535] "Kwh"  PC
 SG_ M2P_SysremEngy_DisChg_B3_08 : 32|16@1+ (1,0) [0|65535] "Kwh"  PC
 SG_ M2P_SysMaxVolt_B3_08 : 48|16@1+ (1,0) [0|65535] "mv"  PC

BO_ 2334322329 M2P_SUMDATA27__09: 8 MBMU
 SG_ M2P_Power_B3_09 : 0|16@1+ (1,-20000) [-20000|45535] "Kw"  PC
 SG_ M2P_SysremEngy_Chg_B3_09 : 16|16@1+ (1,0) [0|65535] "Kwh"  PC
 SG_ M2P_SysremEngy_DisChg_B3_09 : 32|16@1+ (1,0) [0|65535] "Kwh"  PC
 SG_ M2P_SysMaxVolt_B3_09 : 48|16@1+ (1,0) [0|65535] "mv"  PC

BO_ 2334322330 M2P_SUMDATA27__10: 8 MBMU
 SG_ M2P_Power_B3_10 : 0|16@1+ (1,-20000) [-20000|45535] "Kw"  PC
 SG_ M2P_SysremEngy_Chg_B3_10 : 16|16@1+ (1,0) [0|65535] "Kwh"  PC
 SG_ M2P_SysremEngy_DisChg_B3_10 : 32|16@1+ (1,0) [0|65535] "Kwh"  PC
 SG_ M2P_SysMaxVolt_B3_10 : 48|16@1+ (1,0) [0|65535] "mv"  PC

BO_ 2334322331 M2P_SUMDATA27__11: 8 MBMU
 SG_ M2P_Power_B3_11 : 0|16@1+ (1,-20000) [-20000|45535] "Kw"  PC
 SG_ M2P_SysremEngy_Chg_B3_11 : 16|16@1+ (1,0) [0|65535] "Kwh"  PC
 SG_ M2P_SysremEngy_DisChg_B3_11 : 32|16@1+ (1,0) [0|65535] "Kwh"  PC
 SG_ M2P_SysMaxVolt_B3_11 : 48|16@1+ (1,0) [0|65535] "mv"  PC

BO_ 2334322332 M2P_SUMDATA27__12: 8 MBMU
 SG_ M2P_Power_B3_12 : 0|16@1+ (1,-20000) [-20000|45535] "Kw"  PC
 SG_ M2P_SysremEngy_Chg_B3_12 : 16|16@1+ (1,0) [0|65535] "Kwh"  PC
 SG_ M2P_SysremEngy_DisChg_B3_12 : 32|16@1+ (1,0) [0|65535] "Kwh"  PC
 SG_ M2P_SysMaxVolt_B3_12 : 48|16@1+ (1,0) [0|65535] "mv"  PC

BO_ 2334322333 M2P_SUMDATA27__13: 8 MBMU
 SG_ M2P_Power_B3_13 : 0|16@1+ (1,-20000) [-20000|45535] "Kw"  PC
 SG_ M2P_SysremEngy_Chg_B3_13 : 16|16@1+ (1,0) [0|65535] "Kwh"  PC
 SG_ M2P_SysremEngy_DisChg_B3_13 : 32|16@1+ (1,0) [0|65535] "Kwh"  PC
 SG_ M2P_SysMaxVolt_B3_13 : 48|16@1+ (1,0) [0|65535] "mv"  PC

BO_ 2334322334 M2P_SUMDATA27__14: 8 MBMU
 SG_ M2P_Power_B3_14 : 0|16@1+ (1,-20000) [-20000|45535] "Kw"  PC
 SG_ M2P_SysremEngy_Chg_B3_14 : 16|16@1+ (1,0) [0|65535] "Kwh"  PC
 SG_ M2P_SysremEngy_DisChg_B3_14 : 32|16@1+ (1,0) [0|65535] "Kwh"  PC
 SG_ M2P_SysMaxVolt_B3_14 : 48|16@1+ (1,0) [0|65535] "mv"  PC

BO_ 2334322335 M2P_SUMDATA27__15: 8 MBMU
 SG_ M2P_Power_B3_15 : 0|16@1+ (1,-20000) [-20000|45535] "Kw"  PC
 SG_ M2P_SysremEngy_Chg_B3_15 : 16|16@1+ (1,0) [0|65535] "Kwh"  PC
 SG_ M2P_SysremEngy_DisChg_B3_15 : 32|16@1+ (1,0) [0|65535] "Kwh"  PC
 SG_ M2P_SysMaxVolt_B3_15 : 48|16@1+ (1,0) [0|65535] "mv"  PC

BO_ 2334322336 M2P_SUMDATA27__16: 8 MBMU
 SG_ M2P_Power_B3_16 : 0|16@1+ (1,-20000) [-20000|45535] "Kw"  PC
 SG_ M2P_SysremEngy_Chg_B3_16 : 16|16@1+ (1,0) [0|65535] "Kwh"  PC
 SG_ M2P_SysremEngy_DisChg_B3_16 : 32|16@1+ (1,0) [0|65535] "Kwh"  PC
 SG_ M2P_SysMaxVolt_B3_16 : 48|16@1+ (1,0) [0|65535] "mv"  PC

BO_ 2334322337 M2P_SUMDATA27__17: 8 MBMU
 SG_ M2P_Power_B3_17 : 0|16@1+ (1,-20000) [-20000|45535] "Kw"  PC
 SG_ M2P_SysremEngy_Chg_B3_17 : 16|16@1+ (1,0) [0|65535] "Kwh"  PC
 SG_ M2P_SysremEngy_DisChg_B3_17 : 32|16@1+ (1,0) [0|65535] "Kwh"  PC
 SG_ M2P_SysMaxVolt_B3_17 : 48|16@1+ (1,0) [0|65535] "mv"  PC

BO_ 2334322338 M2P_SUMDATA27__18: 8 MBMU
 SG_ M2P_Power_B3_18 : 0|16@1+ (1,-20000) [-20000|45535] "Kw"  PC
 SG_ M2P_SysremEngy_Chg_B3_18 : 16|16@1+ (1,0) [0|65535] "Kwh"  PC
 SG_ M2P_SysremEngy_DisChg_B3_18 : 32|16@1+ (1,0) [0|65535] "Kwh"  PC
 SG_ M2P_SysMaxVolt_B3_18 : 48|16@1+ (1,0) [0|65535] "mv"  PC

BO_ 2334322339 M2P_SUMDATA27__19: 8 MBMU
 SG_ M2P_Power_B3_19 : 0|16@1+ (1,-20000) [-20000|45535] "Kw"  PC
 SG_ M2P_SysremEngy_Chg_B3_19 : 16|16@1+ (1,0) [0|65535] "Kwh"  PC
 SG_ M2P_SysremEngy_DisChg_B3_19 : 32|16@1+ (1,0) [0|65535] "Kwh"  PC
 SG_ M2P_SysMaxVolt_B3_19 : 48|16@1+ (1,0) [0|65535] "mv"  PC

BO_ 2334322340 M2P_SUMDATA27__20: 8 MBMU
 SG_ M2P_Power_B3_20 : 0|16@1+ (1,-20000) [-20000|45535] "Kw"  PC
 SG_ M2P_SysremEngy_Chg_B3_20 : 16|16@1+ (1,0) [0|65535] "Kwh"  PC
 SG_ M2P_SysremEngy_DisChg_B3_20 : 32|16@1+ (1,0) [0|65535] "Kwh"  PC
 SG_ M2P_SysMaxVolt_B3_20 : 48|16@1+ (1,0) [0|65535] "mv"  PC

BO_ 2334322341 M2P_SUMDATA27__21: 8 MBMU
 SG_ M2P_Power_B3_21 : 0|16@1+ (1,-20000) [-20000|45535] "Kw"  PC
 SG_ M2P_SysremEngy_Chg_B3_21 : 16|16@1+ (1,0) [0|65535] "Kwh"  PC
 SG_ M2P_SysremEngy_DisChg_B3_21 : 32|16@1+ (1,0) [0|65535] "Kwh"  PC
 SG_ M2P_SysMaxVolt_B3_21 : 48|16@1+ (1,0) [0|65535] "mv"  PC

BO_ 2334322342 M2P_SUMDATA27__22: 8 MBMU
 SG_ M2P_Power_B3_22 : 0|16@1+ (1,-20000) [-20000|45535] "Kw"  PC
 SG_ M2P_SysremEngy_Chg_B3_22 : 16|16@1+ (1,0) [0|65535] "Kwh"  PC
 SG_ M2P_SysremEngy_DisChg_B3_22 : 32|16@1+ (1,0) [0|65535] "Kwh"  PC
 SG_ M2P_SysMaxVolt_B3_22 : 48|16@1+ (1,0) [0|65535] "mv"  PC

BO_ 2334322343 M2P_SUMDATA27__23: 8 MBMU
 SG_ M2P_Power_B3_23 : 0|16@1+ (1,-20000) [-20000|45535] "Kw"  PC
 SG_ M2P_SysremEngy_Chg_B3_23 : 16|16@1+ (1,0) [0|65535] "Kwh"  PC
 SG_ M2P_SysremEngy_DisChg_B3_23 : 32|16@1+ (1,0) [0|65535] "Kwh"  PC
 SG_ M2P_SysMaxVolt_B3_23 : 48|16@1+ (1,0) [0|65535] "mv"  PC

BO_ 2334322344 M2P_SUMDATA27__24: 8 MBMU
 SG_ M2P_Power_B3_24 : 0|16@1+ (1,-20000) [-20000|45535] "Kw"  PC
 SG_ M2P_SysremEngy_Chg_B3_24 : 16|16@1+ (1,0) [0|65535] "Kwh"  PC
 SG_ M2P_SysremEngy_DisChg_B3_24 : 32|16@1+ (1,0) [0|65535] "Kwh"  PC
 SG_ M2P_SysMaxVolt_B3_24 : 48|16@1+ (1,0) [0|65535] "mv"  PC

BO_ 2334322345 M2P_SUMDATA27__25: 8 MBMU
 SG_ M2P_Power_B3_25 : 0|16@1+ (1,-20000) [-20000|45535] "Kw"  PC
 SG_ M2P_SysremEngy_Chg_B3_25 : 16|16@1+ (1,0) [0|65535] "Kwh"  PC
 SG_ M2P_SysremEngy_DisChg_B3_25 : 32|16@1+ (1,0) [0|65535] "Kwh"  PC
 SG_ M2P_SysMaxVolt_B3_25 : 48|16@1+ (1,0) [0|65535] "mv"  PC

BO_ 2334322346 M2P_SUMDATA27__26: 8 MBMU
 SG_ M2P_Power_B3_26 : 0|16@1+ (1,-20000) [-20000|45535] "Kw"  PC
 SG_ M2P_SysremEngy_Chg_B3_26 : 16|16@1+ (1,0) [0|65535] "Kwh"  PC
 SG_ M2P_SysremEngy_DisChg_B3_26 : 32|16@1+ (1,0) [0|65535] "Kwh"  PC
 SG_ M2P_SysMaxVolt_B3_26 : 48|16@1+ (1,0) [0|65535] "mv"  PC

BO_ 2334322347 M2P_SUMDATA27__27: 8 MBMU
 SG_ M2P_Power_B3_27 : 0|16@1+ (1,-20000) [-20000|45535] "Kw"  PC
 SG_ M2P_SysremEngy_Chg_B3_27 : 16|16@1+ (1,0) [0|65535] "Kwh"  PC
 SG_ M2P_SysremEngy_DisChg_B3_27 : 32|16@1+ (1,0) [0|65535] "Kwh"  PC
 SG_ M2P_SysMaxVolt_B3_27 : 48|16@1+ (1,0) [0|65535] "mv"  PC

BO_ 2334322348 M2P_SUMDATA27__28: 8 MBMU
 SG_ M2P_Power_B3_28 : 0|16@1+ (1,-20000) [-20000|45535] "Kw"  PC
 SG_ M2P_SysremEngy_Chg_B3_28 : 16|16@1+ (1,0) [0|65535] "Kwh"  PC
 SG_ M2P_SysremEngy_DisChg_B3_28 : 32|16@1+ (1,0) [0|65535] "Kwh"  PC
 SG_ M2P_SysMaxVolt_B3_28 : 48|16@1+ (1,0) [0|65535] "mv"  PC

BO_ 2334322349 M2P_SUMDATA27__29: 8 MBMU
 SG_ M2P_Power_B3_29 : 0|16@1+ (1,-20000) [-20000|45535] "Kw"  PC
 SG_ M2P_SysremEngy_Chg_B3_29 : 16|16@1+ (1,0) [0|65535] "Kwh"  PC
 SG_ M2P_SysremEngy_DisChg_B3_29 : 32|16@1+ (1,0) [0|65535] "Kwh"  PC
 SG_ M2P_SysMaxVolt_B3_29 : 48|16@1+ (1,0) [0|65535] "mv"  PC

BO_ 2334322350 M2P_SUMDATA27__30: 8 MBMU
 SG_ M2P_Power_B3_30 : 0|16@1+ (1,-20000) [-20000|45535] "Kw"  PC
 SG_ M2P_SysremEngy_Chg_B3_30 : 16|16@1+ (1,0) [0|65535] "Kwh"  PC
 SG_ M2P_SysremEngy_DisChg_B3_30 : 32|16@1+ (1,0) [0|65535] "Kwh"  PC
 SG_ M2P_SysMaxVolt_B3_30 : 48|16@1+ (1,0) [0|65535] "mv"  PC

BO_ 2334322351 M2P_SUMDATA27__31: 8 MBMU
 SG_ M2P_Power_B3_31 : 0|16@1+ (1,-20000) [-20000|45535] "Kw"  PC
 SG_ M2P_SysremEngy_Chg_B3_31 : 16|16@1+ (1,0) [0|65535] "Kwh"  PC
 SG_ M2P_SysremEngy_DisChg_B3_31 : 32|16@1+ (1,0) [0|65535] "Kwh"  PC
 SG_ M2P_SysMaxVolt_B3_31 : 48|16@1+ (1,0) [0|65535] "mv"  PC

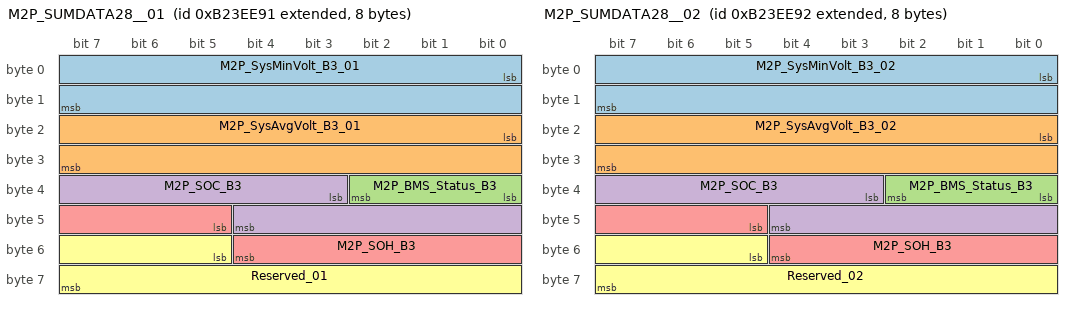
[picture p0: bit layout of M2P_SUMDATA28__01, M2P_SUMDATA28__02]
BO_ 2334387857 M2P_SUMDATA28__01: 8 MBMU
 SG_ M2P_SysMinVolt_B3_01 : 0|16@1+ (1,0) [0|65535] "mv"  PC
 SG_ M2P_SysAvgVolt_B3_01 : 16|16@1+ (1,0) [0|65535] "mv"  PC
 SG_ M2P_BMS_Status_B3 : 32|3@1+ (1,0) [0|7] ""  PC
 SG_ M2P_SOC_B3 : 35|10@1+ (0.1,0) [0|102.3] "%"  PC
 SG_ M2P_SOH_B3 : 45|8@1+ (1,0) [0|255] "%"  PC
 SG_ Reserved_01 : 53|11@1+ (1,0) [0|2047] ""  PC

BO_ 2334387858 M2P_SUMDATA28__02: 8 MBMU
 SG_ M2P_SysMinVolt_B3_02 : 0|16@1+ (1,0) [0|65535] "mv"  PC
 SG_ M2P_SysAvgVolt_B3_02 : 16|16@1+ (1,0) [0|65535] "mv"  PC
 SG_ M2P_BMS_Status_B3 : 32|3@1+ (1,0) [0|7] ""  PC
 SG_ M2P_SOC_B3 : 35|10@1+ (0.1,0) [0|102.3] "%"  PC
 SG_ M2P_SOH_B3 : 45|8@1+ (1,0) [0|255] "%"  PC
 SG_ Reserved_02 : 53|11@1+ (1,0) [0|2047] ""  PC

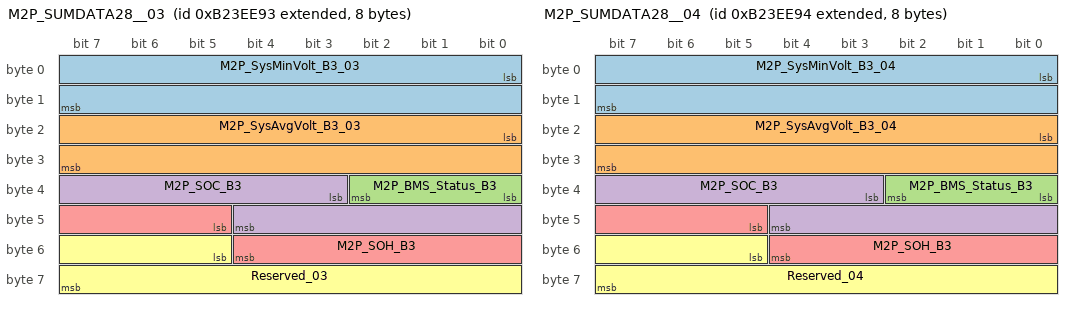
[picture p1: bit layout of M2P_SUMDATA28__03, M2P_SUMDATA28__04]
BO_ 2334387859 M2P_SUMDATA28__03: 8 MBMU
 SG_ M2P_SysMinVolt_B3_03 : 0|16@1+ (1,0) [0|65535] "mv"  PC
 SG_ M2P_SysAvgVolt_B3_03 : 16|16@1+ (1,0) [0|65535] "mv"  PC
 SG_ M2P_BMS_Status_B3 : 32|3@1+ (1,0) [0|7] ""  PC
 SG_ M2P_SOC_B3 : 35|10@1+ (0.1,0) [0|102.3] "%"  PC
 SG_ M2P_SOH_B3 : 45|8@1+ (1,0) [0|255] "%"  PC
 SG_ Reserved_03 : 53|11@1+ (1,0) [0|2047] ""  PC

BO_ 2334387860 M2P_SUMDATA28__04: 8 MBMU
 SG_ M2P_SysMinVolt_B3_04 : 0|16@1+ (1,0) [0|65535] "mv"  PC
 SG_ M2P_SysAvgVolt_B3_04 : 16|16@1+ (1,0) [0|65535] "mv"  PC
 SG_ M2P_BMS_Status_B3 : 32|3@1+ (1,0) [0|7] ""  PC
 SG_ M2P_SOC_B3 : 35|10@1+ (0.1,0) [0|102.3] "%"  PC
 SG_ M2P_SOH_B3 : 45|8@1+ (1,0) [0|255] "%"  PC
 SG_ Reserved_04 : 53|11@1+ (1,0) [0|2047] ""  PC

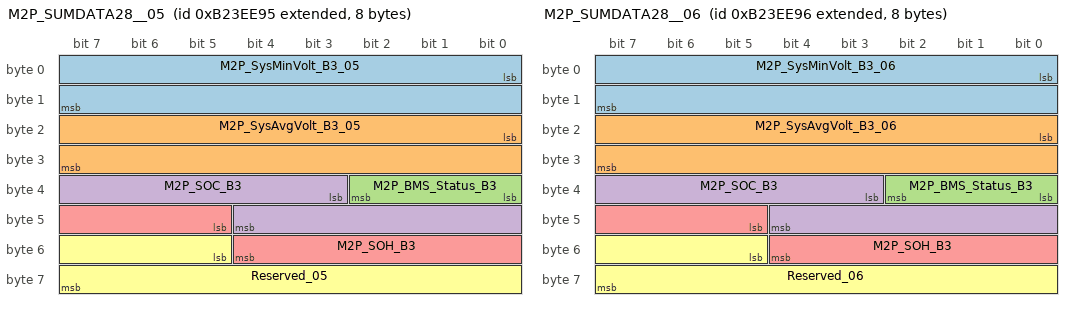
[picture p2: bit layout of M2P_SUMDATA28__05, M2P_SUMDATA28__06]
BO_ 2334387861 M2P_SUMDATA28__05: 8 MBMU
 SG_ M2P_SysMinVolt_B3_05 : 0|16@1+ (1,0) [0|65535] "mv"  PC
 SG_ M2P_SysAvgVolt_B3_05 : 16|16@1+ (1,0) [0|65535] "mv"  PC
 SG_ M2P_BMS_Status_B3 : 32|3@1+ (1,0) [0|7] ""  PC
 SG_ M2P_SOC_B3 : 35|10@1+ (0.1,0) [0|102.3] "%"  PC
 SG_ M2P_SOH_B3 : 45|8@1+ (1,0) [0|255] "%"  PC
 SG_ Reserved_05 : 53|11@1+ (1,0) [0|2047] ""  PC

BO_ 2334387862 M2P_SUMDATA28__06: 8 MBMU
 SG_ M2P_SysMinVolt_B3_06 : 0|16@1+ (1,0) [0|65535] "mv"  PC
 SG_ M2P_SysAvgVolt_B3_06 : 16|16@1+ (1,0) [0|65535] "mv"  PC
 SG_ M2P_BMS_Status_B3 : 32|3@1+ (1,0) [0|7] ""  PC
 SG_ M2P_SOC_B3 : 35|10@1+ (0.1,0) [0|102.3] "%"  PC
 SG_ M2P_SOH_B3 : 45|8@1+ (1,0) [0|255] "%"  PC
 SG_ Reserved_06 : 53|11@1+ (1,0) [0|2047] ""  PC

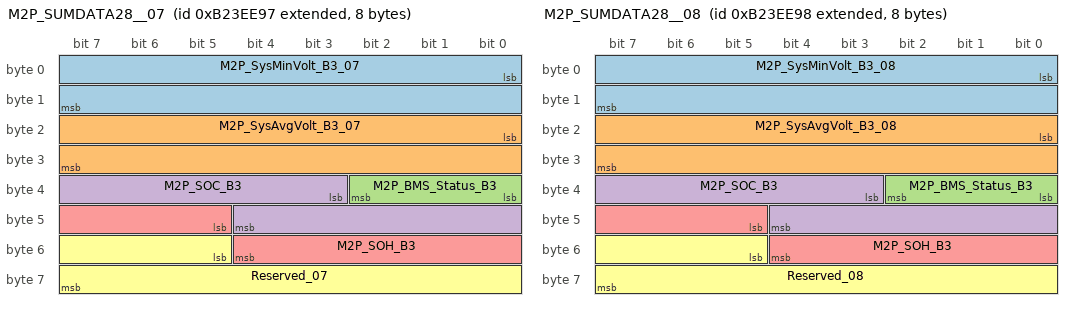
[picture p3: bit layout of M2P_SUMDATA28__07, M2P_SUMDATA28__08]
BO_ 2334387863 M2P_SUMDATA28__07: 8 MBMU
 SG_ M2P_SysMinVolt_B3_07 : 0|16@1+ (1,0) [0|65535] "mv"  PC
 SG_ M2P_SysAvgVolt_B3_07 : 16|16@1+ (1,0) [0|65535] "mv"  PC
 SG_ M2P_BMS_Status_B3 : 32|3@1+ (1,0) [0|7] ""  PC
 SG_ M2P_SOC_B3 : 35|10@1+ (0.1,0) [0|102.3] "%"  PC
 SG_ M2P_SOH_B3 : 45|8@1+ (1,0) [0|255] "%"  PC
 SG_ Reserved_07 : 53|11@1+ (1,0) [0|2047] ""  PC

BO_ 2334387864 M2P_SUMDATA28__08: 8 MBMU
 SG_ M2P_SysMinVolt_B3_08 : 0|16@1+ (1,0) [0|65535] "mv"  PC
 SG_ M2P_SysAvgVolt_B3_08 : 16|16@1+ (1,0) [0|65535] "mv"  PC
 SG_ M2P_BMS_Status_B3 : 32|3@1+ (1,0) [0|7] ""  PC
 SG_ M2P_SOC_B3 : 35|10@1+ (0.1,0) [0|102.3] "%"  PC
 SG_ M2P_SOH_B3 : 45|8@1+ (1,0) [0|255] "%"  PC
 SG_ Reserved_08 : 53|11@1+ (1,0) [0|2047] ""  PC

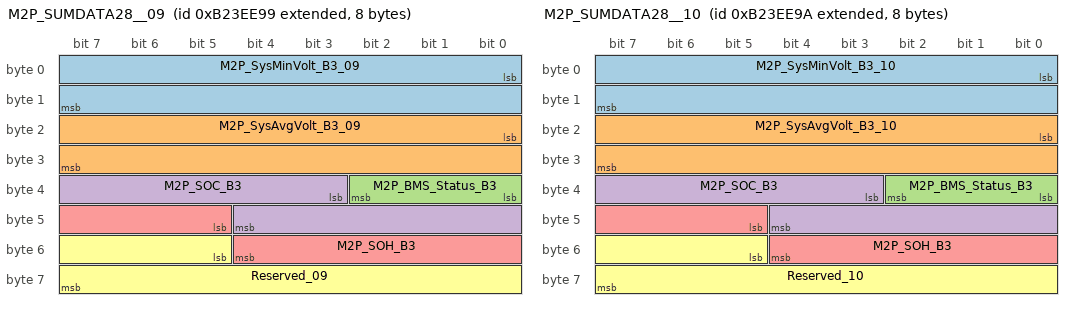
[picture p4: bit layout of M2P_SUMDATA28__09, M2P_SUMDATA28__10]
BO_ 2334387865 M2P_SUMDATA28__09: 8 MBMU
 SG_ M2P_SysMinVolt_B3_09 : 0|16@1+ (1,0) [0|65535] "mv"  PC
 SG_ M2P_SysAvgVolt_B3_09 : 16|16@1+ (1,0) [0|65535] "mv"  PC
 SG_ M2P_BMS_Status_B3 : 32|3@1+ (1,0) [0|7] ""  PC
 SG_ M2P_SOC_B3 : 35|10@1+ (0.1,0) [0|102.3] "%"  PC
 SG_ M2P_SOH_B3 : 45|8@1+ (1,0) [0|255] "%"  PC
 SG_ Reserved_09 : 53|11@1+ (1,0) [0|2047] ""  PC

BO_ 2334387866 M2P_SUMDATA28__10: 8 MBMU
 SG_ M2P_SysMinVolt_B3_10 : 0|16@1+ (1,0) [0|65535] "mv"  PC
 SG_ M2P_SysAvgVolt_B3_10 : 16|16@1+ (1,0) [0|65535] "mv"  PC
 SG_ M2P_BMS_Status_B3 : 32|3@1+ (1,0) [0|7] ""  PC
 SG_ M2P_SOC_B3 : 35|10@1+ (0.1,0) [0|102.3] "%"  PC
 SG_ M2P_SOH_B3 : 45|8@1+ (1,0) [0|255] "%"  PC
 SG_ Reserved_10 : 53|11@1+ (1,0) [0|2047] ""  PC

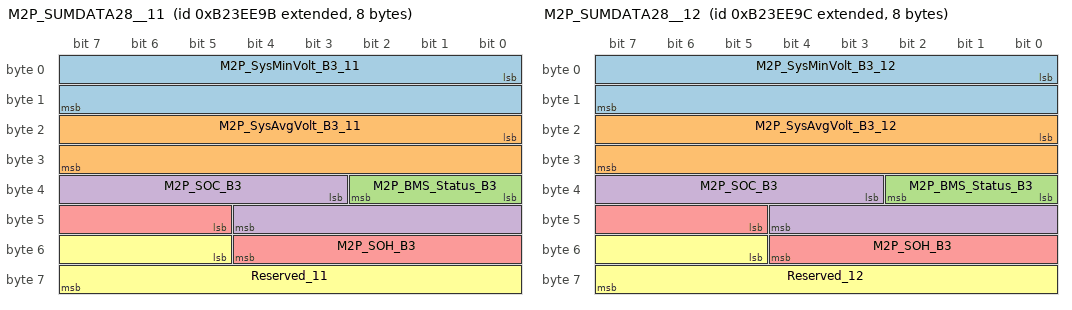
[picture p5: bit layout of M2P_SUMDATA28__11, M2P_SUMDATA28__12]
BO_ 2334387867 M2P_SUMDATA28__11: 8 MBMU
 SG_ M2P_SysMinVolt_B3_11 : 0|16@1+ (1,0) [0|65535] "mv"  PC
 SG_ M2P_SysAvgVolt_B3_11 : 16|16@1+ (1,0) [0|65535] "mv"  PC
 SG_ M2P_BMS_Status_B3 : 32|3@1+ (1,0) [0|7] ""  PC
 SG_ M2P_SOC_B3 : 35|10@1+ (0.1,0) [0|102.3] "%"  PC
 SG_ M2P_SOH_B3 : 45|8@1+ (1,0) [0|255] "%"  PC
 SG_ Reserved_11 : 53|11@1+ (1,0) [0|2047] ""  PC

BO_ 2334387868 M2P_SUMDATA28__12: 8 MBMU
 SG_ M2P_SysMinVolt_B3_12 : 0|16@1+ (1,0) [0|65535] "mv"  PC
 SG_ M2P_SysAvgVolt_B3_12 : 16|16@1+ (1,0) [0|65535] "mv"  PC
 SG_ M2P_BMS_Status_B3 : 32|3@1+ (1,0) [0|7] ""  PC
 SG_ M2P_SOC_B3 : 35|10@1+ (0.1,0) [0|102.3] "%"  PC
 SG_ M2P_SOH_B3 : 45|8@1+ (1,0) [0|255] "%"  PC
 SG_ Reserved_12 : 53|11@1+ (1,0) [0|2047] ""  PC

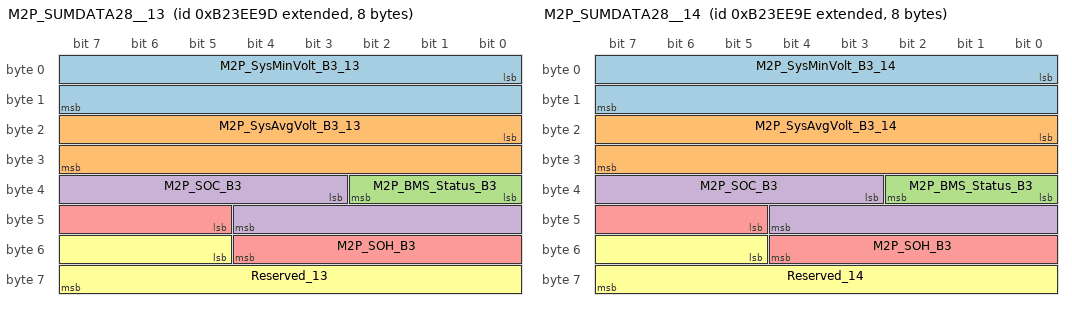
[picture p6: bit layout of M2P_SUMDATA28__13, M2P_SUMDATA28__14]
BO_ 2334387869 M2P_SUMDATA28__13: 8 MBMU
 SG_ M2P_SysMinVolt_B3_13 : 0|16@1+ (1,0) [0|65535] "mv"  PC
 SG_ M2P_SysAvgVolt_B3_13 : 16|16@1+ (1,0) [0|65535] "mv"  PC
 SG_ M2P_BMS_Status_B3 : 32|3@1+ (1,0) [0|7] ""  PC
 SG_ M2P_SOC_B3 : 35|10@1+ (0.1,0) [0|102.3] "%"  PC
 SG_ M2P_SOH_B3 : 45|8@1+ (1,0) [0|255] "%"  PC
 SG_ Reserved_13 : 53|11@1+ (1,0) [0|2047] ""  PC

BO_ 2334387870 M2P_SUMDATA28__14: 8 MBMU
 SG_ M2P_SysMinVolt_B3_14 : 0|16@1+ (1,0) [0|65535] "mv"  PC
 SG_ M2P_SysAvgVolt_B3_14 : 16|16@1+ (1,0) [0|65535] "mv"  PC
 SG_ M2P_BMS_Status_B3 : 32|3@1+ (1,0) [0|7] ""  PC
 SG_ M2P_SOC_B3 : 35|10@1+ (0.1,0) [0|102.3] "%"  PC
 SG_ M2P_SOH_B3 : 45|8@1+ (1,0) [0|255] "%"  PC
 SG_ Reserved_14 : 53|11@1+ (1,0) [0|2047] ""  PC

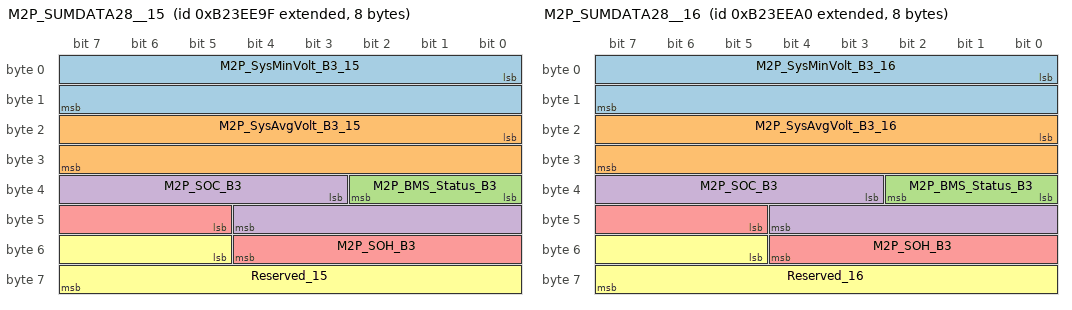
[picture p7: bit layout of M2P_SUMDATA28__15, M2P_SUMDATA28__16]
BO_ 2334387871 M2P_SUMDATA28__15: 8 MBMU
 SG_ M2P_SysMinVolt_B3_15 : 0|16@1+ (1,0) [0|65535] "mv"  PC
 SG_ M2P_SysAvgVolt_B3_15 : 16|16@1+ (1,0) [0|65535] "mv"  PC
 SG_ M2P_BMS_Status_B3 : 32|3@1+ (1,0) [0|7] ""  PC
 SG_ M2P_SOC_B3 : 35|10@1+ (0.1,0) [0|102.3] "%"  PC
 SG_ M2P_SOH_B3 : 45|8@1+ (1,0) [0|255] "%"  PC
 SG_ Reserved_15 : 53|11@1+ (1,0) [0|2047] ""  PC

BO_ 2334387872 M2P_SUMDATA28__16: 8 MBMU
 SG_ M2P_SysMinVolt_B3_16 : 0|16@1+ (1,0) [0|65535] "mv"  PC
 SG_ M2P_SysAvgVolt_B3_16 : 16|16@1+ (1,0) [0|65535] "mv"  PC
 SG_ M2P_BMS_Status_B3 : 32|3@1+ (1,0) [0|7] ""  PC
 SG_ M2P_SOC_B3 : 35|10@1+ (0.1,0) [0|102.3] "%"  PC
 SG_ M2P_SOH_B3 : 45|8@1+ (1,0) [0|255] "%"  PC
 SG_ Reserved_16 : 53|11@1+ (1,0) [0|2047] ""  PC

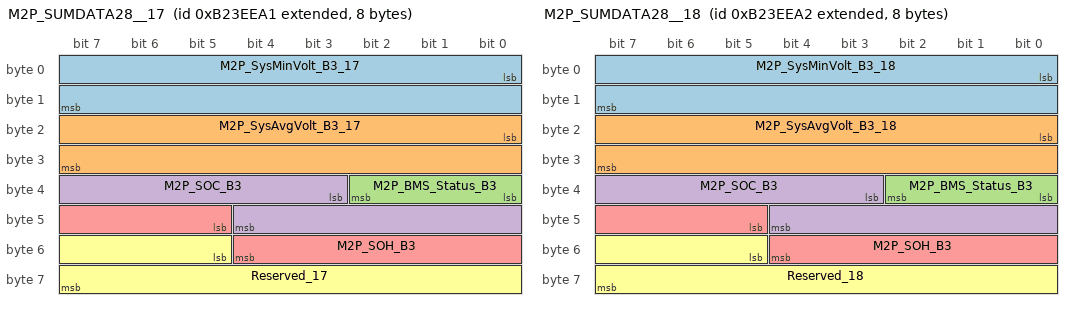
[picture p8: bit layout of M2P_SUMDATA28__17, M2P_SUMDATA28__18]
BO_ 2334387873 M2P_SUMDATA28__17: 8 MBMU
 SG_ M2P_SysMinVolt_B3_17 : 0|16@1+ (1,0) [0|65535] "mv"  PC
 SG_ M2P_SysAvgVolt_B3_17 : 16|16@1+ (1,0) [0|65535] "mv"  PC
 SG_ M2P_BMS_Status_B3 : 32|3@1+ (1,0) [0|7] ""  PC
 SG_ M2P_SOC_B3 : 35|10@1+ (0.1,0) [0|102.3] "%"  PC
 SG_ M2P_SOH_B3 : 45|8@1+ (1,0) [0|255] "%"  PC
 SG_ Reserved_17 : 53|11@1+ (1,0) [0|2047] ""  PC

BO_ 2334387874 M2P_SUMDATA28__18: 8 MBMU
 SG_ M2P_SysMinVolt_B3_18 : 0|16@1+ (1,0) [0|65535] "mv"  PC
 SG_ M2P_SysAvgVolt_B3_18 : 16|16@1+ (1,0) [0|65535] "mv"  PC
 SG_ M2P_BMS_Status_B3 : 32|3@1+ (1,0) [0|7] ""  PC
 SG_ M2P_SOC_B3 : 35|10@1+ (0.1,0) [0|102.3] "%"  PC
 SG_ M2P_SOH_B3 : 45|8@1+ (1,0) [0|255] "%"  PC
 SG_ Reserved_18 : 53|11@1+ (1,0) [0|2047] ""  PC

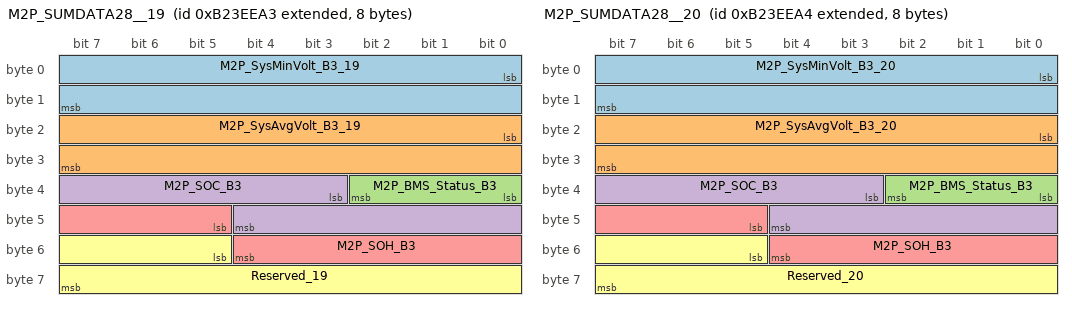
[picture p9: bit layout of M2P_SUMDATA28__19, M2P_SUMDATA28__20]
BO_ 2334387875 M2P_SUMDATA28__19: 8 MBMU
 SG_ M2P_SysMinVolt_B3_19 : 0|16@1+ (1,0) [0|65535] "mv"  PC
 SG_ M2P_SysAvgVolt_B3_19 : 16|16@1+ (1,0) [0|65535] "mv"  PC
 SG_ M2P_BMS_Status_B3 : 32|3@1+ (1,0) [0|7] ""  PC
 SG_ M2P_SOC_B3 : 35|10@1+ (0.1,0) [0|102.3] "%"  PC
 SG_ M2P_SOH_B3 : 45|8@1+ (1,0) [0|255] "%"  PC
 SG_ Reserved_19 : 53|11@1+ (1,0) [0|2047] ""  PC

BO_ 2334387876 M2P_SUMDATA28__20: 8 MBMU
 SG_ M2P_SysMinVolt_B3_20 : 0|16@1+ (1,0) [0|65535] "mv"  PC
 SG_ M2P_SysAvgVolt_B3_20 : 16|16@1+ (1,0) [0|65535] "mv"  PC
 SG_ M2P_BMS_Status_B3 : 32|3@1+ (1,0) [0|7] ""  PC
 SG_ M2P_SOC_B3 : 35|10@1+ (0.1,0) [0|102.3] "%"  PC
 SG_ M2P_SOH_B3 : 45|8@1+ (1,0) [0|255] "%"  PC
 SG_ Reserved_20 : 53|11@1+ (1,0) [0|2047] ""  PC

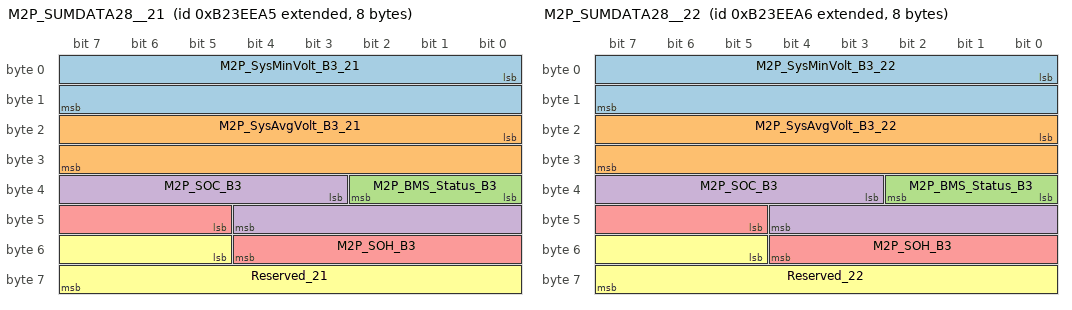
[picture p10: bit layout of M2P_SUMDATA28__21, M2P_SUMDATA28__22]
BO_ 2334387877 M2P_SUMDATA28__21: 8 MBMU
 SG_ M2P_SysMinVolt_B3_21 : 0|16@1+ (1,0) [0|65535] "mv"  PC
 SG_ M2P_SysAvgVolt_B3_21 : 16|16@1+ (1,0) [0|65535] "mv"  PC
 SG_ M2P_BMS_Status_B3 : 32|3@1+ (1,0) [0|7] ""  PC
 SG_ M2P_SOC_B3 : 35|10@1+ (0.1,0) [0|102.3] "%"  PC
 SG_ M2P_SOH_B3 : 45|8@1+ (1,0) [0|255] "%"  PC
 SG_ Reserved_21 : 53|11@1+ (1,0) [0|2047] ""  PC

BO_ 2334387878 M2P_SUMDATA28__22: 8 MBMU
 SG_ M2P_SysMinVolt_B3_22 : 0|16@1+ (1,0) [0|65535] "mv"  PC
 SG_ M2P_SysAvgVolt_B3_22 : 16|16@1+ (1,0) [0|65535] "mv"  PC
 SG_ M2P_BMS_Status_B3 : 32|3@1+ (1,0) [0|7] ""  PC
 SG_ M2P_SOC_B3 : 35|10@1+ (0.1,0) [0|102.3] "%"  PC
 SG_ M2P_SOH_B3 : 45|8@1+ (1,0) [0|255] "%"  PC
 SG_ Reserved_22 : 53|11@1+ (1,0) [0|2047] ""  PC

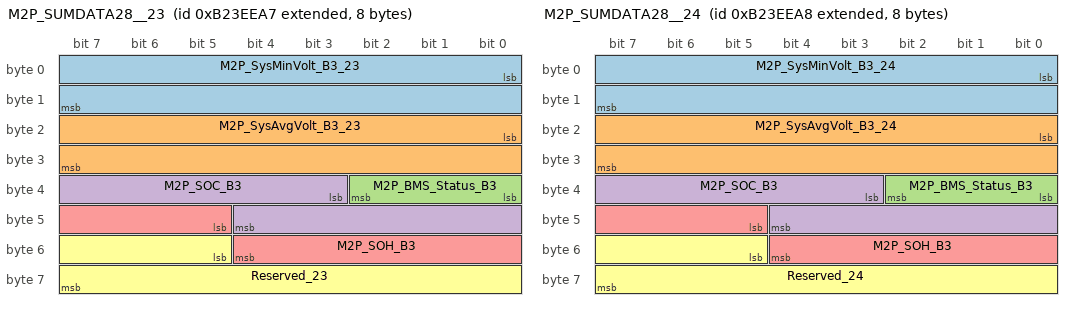
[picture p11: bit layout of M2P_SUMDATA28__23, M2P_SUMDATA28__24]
BO_ 2334387879 M2P_SUMDATA28__23: 8 MBMU
 SG_ M2P_SysMinVolt_B3_23 : 0|16@1+ (1,0) [0|65535] "mv"  PC
 SG_ M2P_SysAvgVolt_B3_23 : 16|16@1+ (1,0) [0|65535] "mv"  PC
 SG_ M2P_BMS_Status_B3 : 32|3@1+ (1,0) [0|7] ""  PC
 SG_ M2P_SOC_B3 : 35|10@1+ (0.1,0) [0|102.3] "%"  PC
 SG_ M2P_SOH_B3 : 45|8@1+ (1,0) [0|255] "%"  PC
 SG_ Reserved_23 : 53|11@1+ (1,0) [0|2047] ""  PC

BO_ 2334387880 M2P_SUMDATA28__24: 8 MBMU
 SG_ M2P_SysMinVolt_B3_24 : 0|16@1+ (1,0) [0|65535] "mv"  PC
 SG_ M2P_SysAvgVolt_B3_24 : 16|16@1+ (1,0) [0|65535] "mv"  PC
 SG_ M2P_BMS_Status_B3 : 32|3@1+ (1,0) [0|7] ""  PC
 SG_ M2P_SOC_B3 : 35|10@1+ (0.1,0) [0|102.3] "%"  PC
 SG_ M2P_SOH_B3 : 45|8@1+ (1,0) [0|255] "%"  PC
 SG_ Reserved_24 : 53|11@1+ (1,0) [0|2047] ""  PC

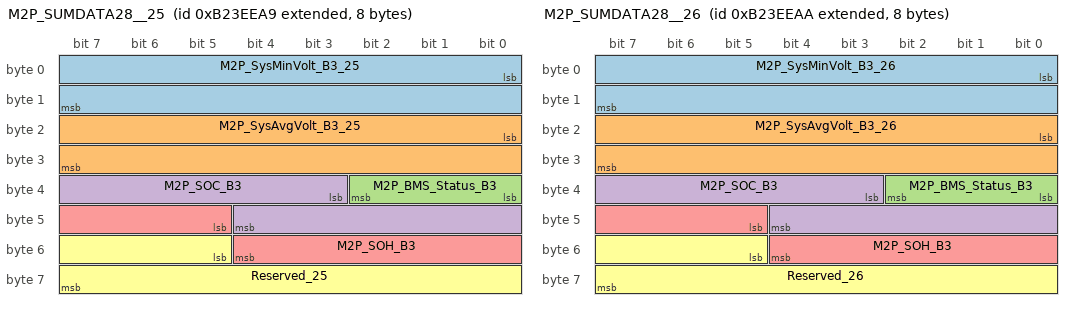
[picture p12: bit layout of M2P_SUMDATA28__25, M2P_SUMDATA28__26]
BO_ 2334387881 M2P_SUMDATA28__25: 8 MBMU
 SG_ M2P_SysMinVolt_B3_25 : 0|16@1+ (1,0) [0|65535] "mv"  PC
 SG_ M2P_SysAvgVolt_B3_25 : 16|16@1+ (1,0) [0|65535] "mv"  PC
 SG_ M2P_BMS_Status_B3 : 32|3@1+ (1,0) [0|7] ""  PC
 SG_ M2P_SOC_B3 : 35|10@1+ (0.1,0) [0|102.3] "%"  PC
 SG_ M2P_SOH_B3 : 45|8@1+ (1,0) [0|255] "%"  PC
 SG_ Reserved_25 : 53|11@1+ (1,0) [0|2047] ""  PC

BO_ 2334387882 M2P_SUMDATA28__26: 8 MBMU
 SG_ M2P_SysMinVolt_B3_26 : 0|16@1+ (1,0) [0|65535] "mv"  PC
 SG_ M2P_SysAvgVolt_B3_26 : 16|16@1+ (1,0) [0|65535] "mv"  PC
 SG_ M2P_BMS_Status_B3 : 32|3@1+ (1,0) [0|7] ""  PC
 SG_ M2P_SOC_B3 : 35|10@1+ (0.1,0) [0|102.3] "%"  PC
 SG_ M2P_SOH_B3 : 45|8@1+ (1,0) [0|255] "%"  PC
 SG_ Reserved_26 : 53|11@1+ (1,0) [0|2047] ""  PC

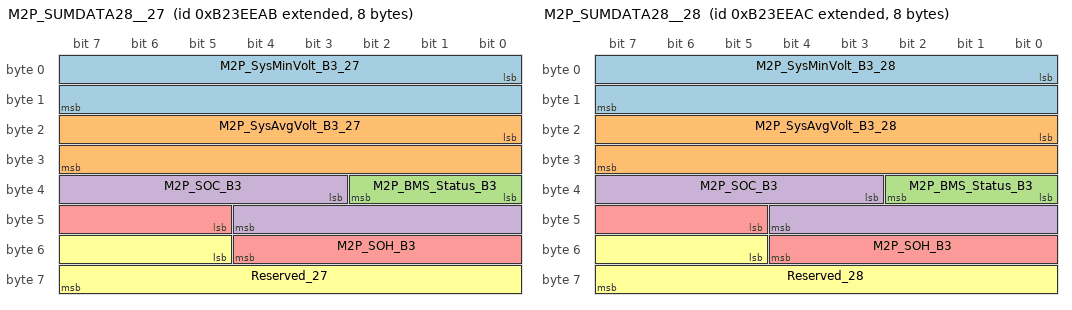
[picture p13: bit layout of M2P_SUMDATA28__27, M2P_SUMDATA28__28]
BO_ 2334387883 M2P_SUMDATA28__27: 8 MBMU
 SG_ M2P_SysMinVolt_B3_27 : 0|16@1+ (1,0) [0|65535] "mv"  PC
 SG_ M2P_SysAvgVolt_B3_27 : 16|16@1+ (1,0) [0|65535] "mv"  PC
 SG_ M2P_BMS_Status_B3 : 32|3@1+ (1,0) [0|7] ""  PC
 SG_ M2P_SOC_B3 : 35|10@1+ (0.1,0) [0|102.3] "%"  PC
 SG_ M2P_SOH_B3 : 45|8@1+ (1,0) [0|255] "%"  PC
 SG_ Reserved_27 : 53|11@1+ (1,0) [0|2047] ""  PC

BO_ 2334387884 M2P_SUMDATA28__28: 8 MBMU
 SG_ M2P_SysMinVolt_B3_28 : 0|16@1+ (1,0) [0|65535] "mv"  PC
 SG_ M2P_SysAvgVolt_B3_28 : 16|16@1+ (1,0) [0|65535] "mv"  PC
 SG_ M2P_BMS_Status_B3 : 32|3@1+ (1,0) [0|7] ""  PC
 SG_ M2P_SOC_B3 : 35|10@1+ (0.1,0) [0|102.3] "%"  PC
 SG_ M2P_SOH_B3 : 45|8@1+ (1,0) [0|255] "%"  PC
 SG_ Reserved_28 : 53|11@1+ (1,0) [0|2047] ""  PC

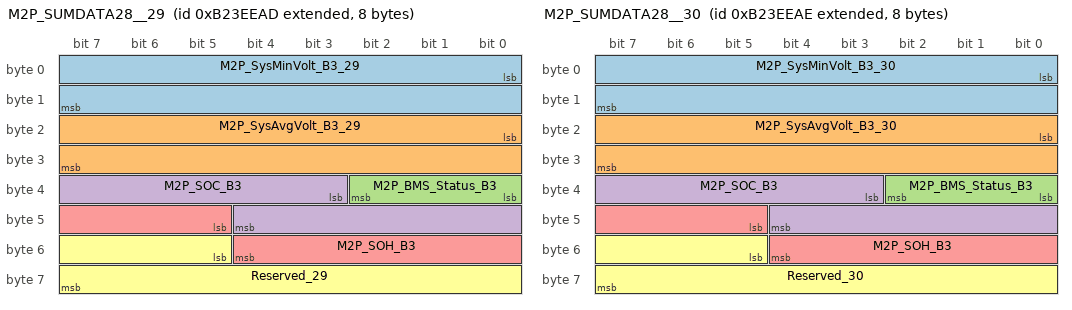
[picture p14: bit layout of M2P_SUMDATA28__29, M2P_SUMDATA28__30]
BO_ 2334387885 M2P_SUMDATA28__29: 8 MBMU
 SG_ M2P_SysMinVolt_B3_29 : 0|16@1+ (1,0) [0|65535] "mv"  PC
 SG_ M2P_SysAvgVolt_B3_29 : 16|16@1+ (1,0) [0|65535] "mv"  PC
 SG_ M2P_BMS_Status_B3 : 32|3@1+ (1,0) [0|7] ""  PC
 SG_ M2P_SOC_B3 : 35|10@1+ (0.1,0) [0|102.3] "%"  PC
 SG_ M2P_SOH_B3 : 45|8@1+ (1,0) [0|255] "%"  PC
 SG_ Reserved_29 : 53|11@1+ (1,0) [0|2047] ""  PC

BO_ 2334387886 M2P_SUMDATA28__30: 8 MBMU
 SG_ M2P_SysMinVolt_B3_30 : 0|16@1+ (1,0) [0|65535] "mv"  PC
 SG_ M2P_SysAvgVolt_B3_30 : 16|16@1+ (1,0) [0|65535] "mv"  PC
 SG_ M2P_BMS_Status_B3 : 32|3@1+ (1,0) [0|7] ""  PC
 SG_ M2P_SOC_B3 : 35|10@1+ (0.1,0) [0|102.3] "%"  PC
 SG_ M2P_SOH_B3 : 45|8@1+ (1,0) [0|255] "%"  PC
 SG_ Reserved_30 : 53|11@1+ (1,0) [0|2047] ""  PC

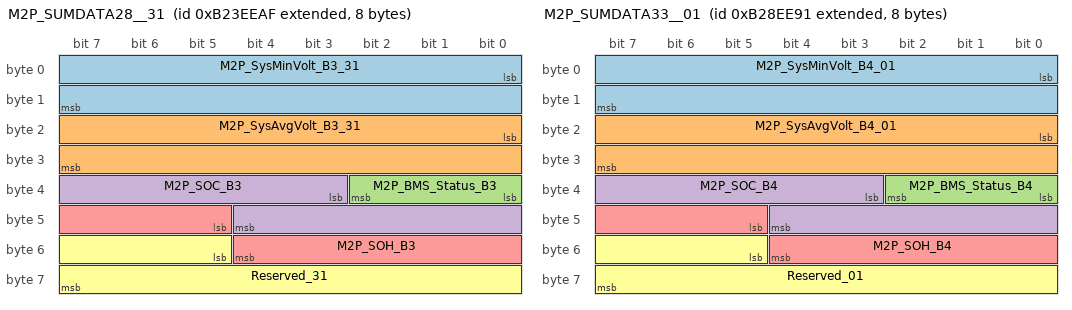
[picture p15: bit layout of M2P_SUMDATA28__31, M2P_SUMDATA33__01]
BO_ 2334387887 M2P_SUMDATA28__31: 8 MBMU
 SG_ M2P_SysMinVolt_B3_31 : 0|16@1+ (1,0) [0|65535] "mv"  PC
 SG_ M2P_SysAvgVolt_B3_31 : 16|16@1+ (1,0) [0|65535] "mv"  PC
 SG_ M2P_BMS_Status_B3 : 32|3@1+ (1,0) [0|7] ""  PC
 SG_ M2P_SOC_B3 : 35|10@1+ (0.1,0) [0|102.3] "%"  PC
 SG_ M2P_SOH_B3 : 45|8@1+ (1,0) [0|255] "%"  PC
 SG_ Reserved_31 : 53|11@1+ (1,0) [0|2047] ""  PC

BO_ 2334453393 M2P_SUMDATA29__01: 8 MBMU
 SG_ M2P_SOE_Charge_B3 : 0|10@1+ (0.1,0) [0|102.3] "%"  PC
 SG_ M2P_SOE_Discharge_B3 : 10|10@1+ (0.1,0) [0|102.3] "%"  PC
 SG_ Reserved_01 : 20|44@1+ (1,0) [0|17592186044415] ""  PC

BO_ 2334453394 M2P_SUMDATA29__02: 8 MBMU
 SG_ M2P_SOE_Charge_B3 : 0|10@1+ (0.1,0) [0|102.3] "%"  PC
 SG_ M2P_SOE_Discharge_B3 : 10|10@1+ (0.1,0) [0|102.3] "%"  PC
 SG_ Reserved_02 : 20|44@1+ (1,0) [0|17592186044415] ""  PC

BO_ 2334453395 M2P_SUMDATA29__03: 8 MBMU
 SG_ M2P_SOE_Charge_B3 : 0|10@1+ (0.1,0) [0|102.3] "%"  PC
 SG_ M2P_SOE_Discharge_B3 : 10|10@1+ (0.1,0) [0|102.3] "%"  PC
 SG_ Reserved_03 : 20|44@1+ (1,0) [0|17592186044415] ""  PC

BO_ 2334453396 M2P_SUMDATA29__04: 8 MBMU
 SG_ M2P_SOE_Charge_B3 : 0|10@1+ (0.1,0) [0|102.3] "%"  PC
 SG_ M2P_SOE_Discharge_B3 : 10|10@1+ (0.1,0) [0|102.3] "%"  PC
 SG_ Reserved_04 : 20|44@1+ (1,0) [0|17592186044415] ""  PC

BO_ 2334453397 M2P_SUMDATA29__05: 8 MBMU
 SG_ M2P_SOE_Charge_B3 : 0|10@1+ (0.1,0) [0|102.3] "%"  PC
 SG_ M2P_SOE_Discharge_B3 : 10|10@1+ (0.1,0) [0|102.3] "%"  PC
 SG_ Reserved_05 : 20|44@1+ (1,0) [0|17592186044415] ""  PC

BO_ 2334453398 M2P_SUMDATA29__06: 8 MBMU
 SG_ M2P_SOE_Charge_B3 : 0|10@1+ (0.1,0) [0|102.3] "%"  PC
 SG_ M2P_SOE_Discharge_B3 : 10|10@1+ (0.1,0) [0|102.3] "%"  PC
 SG_ Reserved_06 : 20|44@1+ (1,0) [0|17592186044415] ""  PC

BO_ 2334453399 M2P_SUMDATA29__07: 8 MBMU
 SG_ M2P_SOE_Charge_B3 : 0|10@1+ (0.1,0) [0|102.3] "%"  PC
 SG_ M2P_SOE_Discharge_B3 : 10|10@1+ (0.1,0) [0|102.3] "%"  PC
 SG_ Reserved_07 : 20|44@1+ (1,0) [0|17592186044415] ""  PC

BO_ 2334453400 M2P_SUMDATA29__08: 8 MBMU
 SG_ M2P_SOE_Charge_B3 : 0|10@1+ (0.1,0) [0|102.3] "%"  PC
 SG_ M2P_SOE_Discharge_B3 : 10|10@1+ (0.1,0) [0|102.3] "%"  PC
 SG_ Reserved_08 : 20|44@1+ (1,0) [0|17592186044415] ""  PC

BO_ 2334453401 M2P_SUMDATA29__09: 8 MBMU
 SG_ M2P_SOE_Charge_B3 : 0|10@1+ (0.1,0) [0|102.3] "%"  PC
 SG_ M2P_SOE_Discharge_B3 : 10|10@1+ (0.1,0) [0|102.3] "%"  PC
 SG_ Reserved_09 : 20|44@1+ (1,0) [0|17592186044415] ""  PC

BO_ 2334453402 M2P_SUMDATA29__10: 8 MBMU
 SG_ M2P_SOE_Charge_B3 : 0|10@1+ (0.1,0) [0|102.3] "%"  PC
 SG_ M2P_SOE_Discharge_B3 : 10|10@1+ (0.1,0) [0|102.3] "%"  PC
 SG_ Reserved_10 : 20|44@1+ (1,0) [0|17592186044415] ""  PC

BO_ 2334453403 M2P_SUMDATA29__11: 8 MBMU
 SG_ M2P_SOE_Charge_B3 : 0|10@1+ (0.1,0) [0|102.3] "%"  PC
 SG_ M2P_SOE_Discharge_B3 : 10|10@1+ (0.1,0) [0|102.3] "%"  PC
 SG_ Reserved_11 : 20|44@1+ (1,0) [0|17592186044415] ""  PC

BO_ 2334453404 M2P_SUMDATA29__12: 8 MBMU
 SG_ M2P_SOE_Charge_B3 : 0|10@1+ (0.1,0) [0|102.3] "%"  PC
 SG_ M2P_SOE_Discharge_B3 : 10|10@1+ (0.1,0) [0|102.3] "%"  PC
 SG_ Reserved_12 : 20|44@1+ (1,0) [0|17592186044415] ""  PC

BO_ 2334453405 M2P_SUMDATA29__13: 8 MBMU
 SG_ M2P_SOE_Charge_B3 : 0|10@1+ (0.1,0) [0|102.3] "%"  PC
 SG_ M2P_SOE_Discharge_B3 : 10|10@1+ (0.1,0) [0|102.3] "%"  PC
 SG_ Reserved_13 : 20|44@1+ (1,0) [0|17592186044415] ""  PC

BO_ 2334453406 M2P_SUMDATA29__14: 8 MBMU
 SG_ M2P_SOE_Charge_B3 : 0|10@1+ (0.1,0) [0|102.3] "%"  PC
 SG_ M2P_SOE_Discharge_B3 : 10|10@1+ (0.1,0) [0|102.3] "%"  PC
 SG_ Reserved_14 : 20|44@1+ (1,0) [0|17592186044415] ""  PC

BO_ 2334453407 M2P_SUMDATA29__15: 8 MBMU
 SG_ M2P_SOE_Charge_B3 : 0|10@1+ (0.1,0) [0|102.3] "%"  PC
 SG_ M2P_SOE_Discharge_B3 : 10|10@1+ (0.1,0) [0|102.3] "%"  PC
 SG_ Reserved_15 : 20|44@1+ (1,0) [0|17592186044415] ""  PC

BO_ 2334453408 M2P_SUMDATA29__16: 8 MBMU
 SG_ M2P_SOE_Charge_B3 : 0|10@1+ (0.1,0) [0|102.3] "%"  PC
 SG_ M2P_SOE_Discharge_B3 : 10|10@1+ (0.1,0) [0|102.3] "%"  PC
 SG_ Reserved_16 : 20|44@1+ (1,0) [0|17592186044415] ""  PC

BO_ 2334453409 M2P_SUMDATA29__17: 8 MBMU
 SG_ M2P_SOE_Charge_B3 : 0|10@1+ (0.1,0) [0|102.3] "%"  PC
 SG_ M2P_SOE_Discharge_B3 : 10|10@1+ (0.1,0) [0|102.3] "%"  PC
 SG_ Reserved_17 : 20|44@1+ (1,0) [0|17592186044415] ""  PC

BO_ 2334453410 M2P_SUMDATA29__18: 8 MBMU
 SG_ M2P_SOE_Charge_B3 : 0|10@1+ (0.1,0) [0|102.3] "%"  PC
 SG_ M2P_SOE_Discharge_B3 : 10|10@1+ (0.1,0) [0|102.3] "%"  PC
 SG_ Reserved_18 : 20|44@1+ (1,0) [0|17592186044415] ""  PC

BO_ 2334453411 M2P_SUMDATA29__19: 8 MBMU
 SG_ M2P_SOE_Charge_B3 : 0|10@1+ (0.1,0) [0|102.3] "%"  PC
 SG_ M2P_SOE_Discharge_B3 : 10|10@1+ (0.1,0) [0|102.3] "%"  PC
 SG_ Reserved_19 : 20|44@1+ (1,0) [0|17592186044415] ""  PC

BO_ 2334453412 M2P_SUMDATA29__20: 8 MBMU
 SG_ M2P_SOE_Charge_B3 : 0|10@1+ (0.1,0) [0|102.3] "%"  PC
 SG_ M2P_SOE_Discharge_B3 : 10|10@1+ (0.1,0) [0|102.3] "%"  PC
 SG_ Reserved_20 : 20|44@1+ (1,0) [0|17592186044415] ""  PC

BO_ 2334453413 M2P_SUMDATA29__21: 8 MBMU
 SG_ M2P_SOE_Charge_B3 : 0|10@1+ (0.1,0) [0|102.3] "%"  PC
 SG_ M2P_SOE_Discharge_B3 : 10|10@1+ (0.1,0) [0|102.3] "%"  PC
 SG_ Reserved_21 : 20|44@1+ (1,0) [0|17592186044415] ""  PC

BO_ 2334453414 M2P_SUMDATA29__22: 8 MBMU
 SG_ M2P_SOE_Charge_B3 : 0|10@1+ (0.1,0) [0|102.3] "%"  PC
 SG_ M2P_SOE_Discharge_B3 : 10|10@1+ (0.1,0) [0|102.3] "%"  PC
 SG_ Reserved_22 : 20|44@1+ (1,0) [0|17592186044415] ""  PC

BO_ 2334453415 M2P_SUMDATA29__23: 8 MBMU
 SG_ M2P_SOE_Charge_B3 : 0|10@1+ (0.1,0) [0|102.3] "%"  PC
 SG_ M2P_SOE_Discharge_B3 : 10|10@1+ (0.1,0) [0|102.3] "%"  PC
 SG_ Reserved_23 : 20|44@1+ (1,0) [0|17592186044415] ""  PC

BO_ 2334453416 M2P_SUMDATA29__24: 8 MBMU
 SG_ M2P_SOE_Charge_B3 : 0|10@1+ (0.1,0) [0|102.3] "%"  PC
 SG_ M2P_SOE_Discharge_B3 : 10|10@1+ (0.1,0) [0|102.3] "%"  PC
 SG_ Reserved_24 : 20|44@1+ (1,0) [0|17592186044415] ""  PC

BO_ 2334453417 M2P_SUMDATA29__25: 8 MBMU
 SG_ M2P_SOE_Charge_B3 : 0|10@1+ (0.1,0) [0|102.3] "%"  PC
 SG_ M2P_SOE_Discharge_B3 : 10|10@1+ (0.1,0) [0|102.3] "%"  PC
 SG_ Reserved_25 : 20|44@1+ (1,0) [0|17592186044415] ""  PC

BO_ 2334453418 M2P_SUMDATA29__26: 8 MBMU
 SG_ M2P_SOE_Charge_B3 : 0|10@1+ (0.1,0) [0|102.3] "%"  PC
 SG_ M2P_SOE_Discharge_B3 : 10|10@1+ (0.1,0) [0|102.3] "%"  PC
 SG_ Reserved_26 : 20|44@1+ (1,0) [0|17592186044415] ""  PC

BO_ 2334453419 M2P_SUMDATA29__27: 8 MBMU
 SG_ M2P_SOE_Charge_B3 : 0|10@1+ (0.1,0) [0|102.3] "%"  PC
 SG_ M2P_SOE_Discharge_B3 : 10|10@1+ (0.1,0) [0|102.3] "%"  PC
 SG_ Reserved_27 : 20|44@1+ (1,0) [0|17592186044415] ""  PC

BO_ 2334453420 M2P_SUMDATA29__28: 8 MBMU
 SG_ M2P_SOE_Charge_B3 : 0|10@1+ (0.1,0) [0|102.3] "%"  PC
 SG_ M2P_SOE_Discharge_B3 : 10|10@1+ (0.1,0) [0|102.3] "%"  PC
 SG_ Reserved_28 : 20|44@1+ (1,0) [0|17592186044415] ""  PC

BO_ 2334453421 M2P_SUMDATA29__29: 8 MBMU
 SG_ M2P_SOE_Charge_B3 : 0|10@1+ (0.1,0) [0|102.3] "%"  PC
 SG_ M2P_SOE_Discharge_B3 : 10|10@1+ (0.1,0) [0|102.3] "%"  PC
 SG_ Reserved_29 : 20|44@1+ (1,0) [0|17592186044415] ""  PC

BO_ 2334453422 M2P_SUMDATA29__30: 8 MBMU
 SG_ M2P_SOE_Charge_B3 : 0|10@1+ (0.1,0) [0|102.3] "%"  PC
 SG_ M2P_SOE_Discharge_B3 : 10|10@1+ (0.1,0) [0|102.3] "%"  PC
 SG_ Reserved_30 : 20|44@1+ (1,0) [0|17592186044415] ""  PC

BO_ 2334453423 M2P_SUMDATA29__31: 8 MBMU
 SG_ M2P_SOE_Charge_B3 : 0|10@1+ (0.1,0) [0|102.3] "%"  PC
 SG_ M2P_SOE_Discharge_B3 : 10|10@1+ (0.1,0) [0|102.3] "%"  PC
 SG_ Reserved_31 : 20|44@1+ (1,0) [0|17592186044415] ""  PC

BO_ 2334518929 M2P_SUMDATA30__01: 8 MBMU
 SG_ M2P_Measure_Vol_B4_01 : 0|16@1+ (0.1,0) [0|6553.5] "V"  PC,SBMU
 SG_ M2P_Current_B4_01 : 16|16@1+ (1,-20000) [-20000|45535] "A"  PC,SBMU
 SG_ M2P_PermitMaxCharge_I_B4_01 : 32|16@1+ (1,-20000) [-20000|45535] "A"  PC
 SG_ M2P_PermitMaxDisCharge_I_B4_01 : 48|16@1+ (1,-20000) [-20000|45535] "A"  PC

BO_ 2334518930 M2P_SUMDATA30__02: 8 MBMU
 SG_ M2P_Measure_Vol_B4_02 : 0|16@1+ (0.1,0) [0|6553.5] "V"  PC,SBMU
 SG_ M2P_Current_B4_02 : 16|16@1+ (1,-20000) [-20000|45535] "A"  PC,SBMU
 SG_ M2P_PermitMaxCharge_I_B4_02 : 32|16@1+ (1,-20000) [-20000|45535] "A"  PC
 SG_ M2P_PermitMaxDisCharge_I_B4_02 : 48|16@1+ (1,-20000) [-20000|45535] "A"  PC

BO_ 2334518931 M2P_SUMDATA30__03: 8 MBMU
 SG_ M2P_Measure_Vol_B4_03 : 0|16@1+ (0.1,0) [0|6553.5] "V"  PC,SBMU
 SG_ M2P_Current_B4_03 : 16|16@1+ (1,-20000) [-20000|45535] "A"  PC,SBMU
 SG_ M2P_PermitMaxCharge_I_B4_03 : 32|16@1+ (1,-20000) [-20000|45535] "A"  PC
 SG_ M2P_PermitMaxDisCharge_I_B4_03 : 48|16@1+ (1,-20000) [-20000|45535] "A"  PC

BO_ 2334518932 M2P_SUMDATA30__04: 8 MBMU
 SG_ M2P_Measure_Vol_B4_04 : 0|16@1+ (0.1,0) [0|6553.5] "V"  PC,SBMU
 SG_ M2P_Current_B4_04 : 16|16@1+ (1,-20000) [-20000|45535] "A"  PC,SBMU
 SG_ M2P_PermitMaxCharge_I_B4_04 : 32|16@1+ (1,-20000) [-20000|45535] "A"  PC
 SG_ M2P_PermitMaxDisCharge_I_B4_04 : 48|16@1+ (1,-20000) [-20000|45535] "A"  PC

BO_ 2334518933 M2P_SUMDATA30__05: 8 MBMU
 SG_ M2P_Measure_Vol_B4_05 : 0|16@1+ (0.1,0) [0|6553.5] "V"  PC,SBMU
 SG_ M2P_Current_B4_05 : 16|16@1+ (1,-20000) [-20000|45535] "A"  PC,SBMU
 SG_ M2P_PermitMaxCharge_I_B4_05 : 32|16@1+ (1,-20000) [-20000|45535] "A"  PC
 SG_ M2P_PermitMaxDisCharge_I_B4_05 : 48|16@1+ (1,-20000) [-20000|45535] "A"  PC

BO_ 2334518934 M2P_SUMDATA30__06: 8 MBMU
 SG_ M2P_Measure_Vol_B4_06 : 0|16@1+ (0.1,0) [0|6553.5] "V"  PC,SBMU
 SG_ M2P_Current_B4_06 : 16|16@1+ (1,-20000) [-20000|45535] "A"  PC,SBMU
 SG_ M2P_PermitMaxCharge_I_B4_06 : 32|16@1+ (1,-20000) [-20000|45535] "A"  PC
 SG_ M2P_PermitMaxDisCharge_I_B4_06 : 48|16@1+ (1,-20000) [-20000|45535] "A"  PC

BO_ 2334518935 M2P_SUMDATA30__07: 8 MBMU
 SG_ M2P_Measure_Vol_B4_07 : 0|16@1+ (0.1,0) [0|6553.5] "V"  PC,SBMU
 SG_ M2P_Current_B4_07 : 16|16@1+ (1,-20000) [-20000|45535] "A"  PC,SBMU
 SG_ M2P_PermitMaxCharge_I_B4_07 : 32|16@1+ (1,-20000) [-20000|45535] "A"  PC
 SG_ M2P_PermitMaxDisCharge_I_B4_07 : 48|16@1+ (1,-20000) [-20000|45535] "A"  PC

BO_ 2334518936 M2P_SUMDATA30__08: 8 MBMU
 SG_ M2P_Measure_Vol_B4_08 : 0|16@1+ (0.1,0) [0|6553.5] "V"  PC,SBMU
 SG_ M2P_Current_B4_08 : 16|16@1+ (1,-20000) [-20000|45535] "A"  PC,SBMU
 SG_ M2P_PermitMaxCharge_I_B4_08 : 32|16@1+ (1,-20000) [-20000|45535] "A"  PC
 SG_ M2P_PermitMaxDisCharge_I_B4_08 : 48|16@1+ (1,-20000) [-20000|45535] "A"  PC

BO_ 2334518937 M2P_SUMDATA30__09: 8 MBMU
 SG_ M2P_Measure_Vol_B4_09 : 0|16@1+ (0.1,0) [0|6553.5] "V"  PC,SBMU
 SG_ M2P_Current_B4_09 : 16|16@1+ (1,-20000) [-20000|45535] "A"  PC,SBMU
 SG_ M2P_PermitMaxCharge_I_B4_09 : 32|16@1+ (1,-20000) [-20000|45535] "A"  PC
 SG_ M2P_PermitMaxDisCharge_I_B4_09 : 48|16@1+ (1,-20000) [-20000|45535] "A"  PC

BO_ 2334518938 M2P_SUMDATA30__10: 8 MBMU
 SG_ M2P_Measure_Vol_B4_10 : 0|16@1+ (0.1,0) [0|6553.5] "V"  PC,SBMU
 SG_ M2P_Current_B4_10 : 16|16@1+ (1,-20000) [-20000|45535] "A"  PC,SBMU
 SG_ M2P_PermitMaxCharge_I_B4_10 : 32|16@1+ (1,-20000) [-20000|45535] "A"  PC
 SG_ M2P_PermitMaxDisCharge_I_B4_10 : 48|16@1+ (1,-20000) [-20000|45535] "A"  PC

BO_ 2334518939 M2P_SUMDATA30__11: 8 MBMU
 SG_ M2P_Measure_Vol_B4_11 : 0|16@1+ (0.1,0) [0|6553.5] "V"  PC,SBMU
 SG_ M2P_Current_B4_11 : 16|16@1+ (1,-20000) [-20000|45535] "A"  PC,SBMU
 SG_ M2P_PermitMaxCharge_I_B4_11 : 32|16@1+ (1,-20000) [-20000|45535] "A"  PC
 SG_ M2P_PermitMaxDisCharge_I_B4_11 : 48|16@1+ (1,-20000) [-20000|45535] "A"  PC

BO_ 2334518940 M2P_SUMDATA30__12: 8 MBMU
 SG_ M2P_Measure_Vol_B4_12 : 0|16@1+ (0.1,0) [0|6553.5] "V"  PC,SBMU
 SG_ M2P_Current_B4_12 : 16|16@1+ (1,-20000) [-20000|45535] "A"  PC,SBMU
 SG_ M2P_PermitMaxCharge_I_B4_12 : 32|16@1+ (1,-20000) [-20000|45535] "A"  PC
 SG_ M2P_PermitMaxDisCharge_I_B4_12 : 48|16@1+ (1,-20000) [-20000|45535] "A"  PC

BO_ 2334518941 M2P_SUMDATA30__13: 8 MBMU
 SG_ M2P_Measure_Vol_B4_13 : 0|16@1+ (0.1,0) [0|6553.5] "V"  PC,SBMU
 SG_ M2P_Current_B4_13 : 16|16@1+ (1,-20000) [-20000|45535] "A"  PC,SBMU
 SG_ M2P_PermitMaxCharge_I_B4_13 : 32|16@1+ (1,-20000) [-20000|45535] "A"  PC
 SG_ M2P_PermitMaxDisCharge_I_B4_13 : 48|16@1+ (1,-20000) [-20000|45535] "A"  PC

BO_ 2334518942 M2P_SUMDATA30__14: 8 MBMU
 SG_ M2P_Measure_Vol_B4_14 : 0|16@1+ (0.1,0) [0|6553.5] "V"  PC,SBMU
 SG_ M2P_Current_B4_14 : 16|16@1+ (1,-20000) [-20000|45535] "A"  PC,SBMU
 SG_ M2P_PermitMaxCharge_I_B4_14 : 32|16@1+ (1,-20000) [-20000|45535] "A"  PC
 SG_ M2P_PermitMaxDisCharge_I_B4_14 : 48|16@1+ (1,-20000) [-20000|45535] "A"  PC

BO_ 2334518943 M2P_SUMDATA30__15: 8 MBMU
 SG_ M2P_Measure_Vol_B4_15 : 0|16@1+ (0.1,0) [0|6553.5] "V"  PC,SBMU
 SG_ M2P_Current_B4_15 : 16|16@1+ (1,-20000) [-20000|45535] "A"  PC,SBMU
 SG_ M2P_PermitMaxCharge_I_B4_15 : 32|16@1+ (1,-20000) [-20000|45535] "A"  PC
 SG_ M2P_PermitMaxDisCharge_I_B4_15 : 48|16@1+ (1,-20000) [-20000|45535] "A"  PC

BO_ 2334518944 M2P_SUMDATA30__16: 8 MBMU
 SG_ M2P_Measure_Vol_B4_16 : 0|16@1+ (0.1,0) [0|6553.5] "V"  PC,SBMU
 SG_ M2P_Current_B4_16 : 16|16@1+ (1,-20000) [-20000|45535] "A"  PC,SBMU
 SG_ M2P_PermitMaxCharge_I_B4_16 : 32|16@1+ (1,-20000) [-20000|45535] "A"  PC
 SG_ M2P_PermitMaxDisCharge_I_B4_16 : 48|16@1+ (1,-20000) [-20000|45535] "A"  PC

BO_ 2334518945 M2P_SUMDATA30__17: 8 MBMU
 SG_ M2P_Measure_Vol_B4_17 : 0|16@1+ (0.1,0) [0|6553.5] "V"  PC,SBMU
 SG_ M2P_Current_B4_17 : 16|16@1+ (1,-20000) [-20000|45535] "A"  PC,SBMU
 SG_ M2P_PermitMaxCharge_I_B4_17 : 32|16@1+ (1,-20000) [-20000|45535] "A"  PC
 SG_ M2P_PermitMaxDisCharge_I_B4_17 : 48|16@1+ (1,-20000) [-20000|45535] "A"  PC

BO_ 2334518946 M2P_SUMDATA30__18: 8 MBMU
 SG_ M2P_Measure_Vol_B4_18 : 0|16@1+ (0.1,0) [0|6553.5] "V"  PC,SBMU
 SG_ M2P_Current_B4_18 : 16|16@1+ (1,-20000) [-20000|45535] "A"  PC,SBMU
 SG_ M2P_PermitMaxCharge_I_B4_18 : 32|16@1+ (1,-20000) [-20000|45535] "A"  PC
 SG_ M2P_PermitMaxDisCharge_I_B4_18 : 48|16@1+ (1,-20000) [-20000|45535] "A"  PC

BO_ 2334518947 M2P_SUMDATA30__19: 8 MBMU
 SG_ M2P_Measure_Vol_B4_19 : 0|16@1+ (0.1,0) [0|6553.5] "V"  PC,SBMU
 SG_ M2P_Current_B4_19 : 16|16@1+ (1,-20000) [-20000|45535] "A"  PC,SBMU
 SG_ M2P_PermitMaxCharge_I_B4_19 : 32|16@1+ (1,-20000) [-20000|45535] "A"  PC
 SG_ M2P_PermitMaxDisCharge_I_B4_19 : 48|16@1+ (1,-20000) [-20000|45535] "A"  PC

BO_ 2334518948 M2P_SUMDATA30__20: 8 MBMU
 SG_ M2P_Measure_Vol_B4_20 : 0|16@1+ (0.1,0) [0|6553.5] "V"  PC,SBMU
 SG_ M2P_Current_B4_20 : 16|16@1+ (1,-20000) [-20000|45535] "A"  PC,SBMU
 SG_ M2P_PermitMaxCharge_I_B4_20 : 32|16@1+ (1,-20000) [-20000|45535] "A"  PC
 SG_ M2P_PermitMaxDisCharge_I_B4_20 : 48|16@1+ (1,-20000) [-20000|45535] "A"  PC

BO_ 2334518949 M2P_SUMDATA30__21: 8 MBMU
 SG_ M2P_Measure_Vol_B4_21 : 0|16@1+ (0.1,0) [0|6553.5] "V"  PC,SBMU
 SG_ M2P_Current_B4_21 : 16|16@1+ (1,-20000) [-20000|45535] "A"  PC,SBMU
 SG_ M2P_PermitMaxCharge_I_B4_21 : 32|16@1+ (1,-20000) [-20000|45535] "A"  PC
 SG_ M2P_PermitMaxDisCharge_I_B4_21 : 48|16@1+ (1,-20000) [-20000|45535] "A"  PC

BO_ 2334518950 M2P_SUMDATA30__22: 8 MBMU
 SG_ M2P_Measure_Vol_B4_22 : 0|16@1+ (0.1,0) [0|6553.5] "V"  PC,SBMU
 SG_ M2P_Current_B4_22 : 16|16@1+ (1,-20000) [-20000|45535] "A"  PC,SBMU
 SG_ M2P_PermitMaxCharge_I_B4_22 : 32|16@1+ (1,-20000) [-20000|45535] "A"  PC
 SG_ M2P_PermitMaxDisCharge_I_B4_22 : 48|16@1+ (1,-20000) [-20000|45535] "A"  PC

BO_ 2334518951 M2P_SUMDATA30__23: 8 MBMU
 SG_ M2P_Measure_Vol_B4_23 : 0|16@1+ (0.1,0) [0|6553.5] "V"  PC,SBMU
 SG_ M2P_Current_B4_23 : 16|16@1+ (1,-20000) [-20000|45535] "A"  PC,SBMU
 SG_ M2P_PermitMaxCharge_I_B4_23 : 32|16@1+ (1,-20000) [-20000|45535] "A"  PC
 SG_ M2P_PermitMaxDisCharge_I_B4_23 : 48|16@1+ (1,-20000) [-20000|45535] "A"  PC

BO_ 2334518952 M2P_SUMDATA30__24: 8 MBMU
 SG_ M2P_Measure_Vol_B4_24 : 0|16@1+ (0.1,0) [0|6553.5] "V"  PC,SBMU
 SG_ M2P_Current_B4_24 : 16|16@1+ (1,-20000) [-20000|45535] "A"  PC,SBMU
 SG_ M2P_PermitMaxCharge_I_B4_24 : 32|16@1+ (1,-20000) [-20000|45535] "A"  PC
 SG_ M2P_PermitMaxDisCharge_I_B4_24 : 48|16@1+ (1,-20000) [-20000|45535] "A"  PC

BO_ 2334518953 M2P_SUMDATA30__25: 8 MBMU
 SG_ M2P_Measure_Vol_B4_25 : 0|16@1+ (0.1,0) [0|6553.5] "V"  PC,SBMU
 SG_ M2P_Current_B4_25 : 16|16@1+ (1,-20000) [-20000|45535] "A"  PC,SBMU
 SG_ M2P_PermitMaxCharge_I_B4_25 : 32|16@1+ (1,-20000) [-20000|45535] "A"  PC
 SG_ M2P_PermitMaxDisCharge_I_B4_25 : 48|16@1+ (1,-20000) [-20000|45535] "A"  PC

BO_ 2334518954 M2P_SUMDATA30__26: 8 MBMU
 SG_ M2P_Measure_Vol_B4_26 : 0|16@1+ (0.1,0) [0|6553.5] "V"  PC,SBMU
 SG_ M2P_Current_B4_26 : 16|16@1+ (1,-20000) [-20000|45535] "A"  PC,SBMU
 SG_ M2P_PermitMaxCharge_I_B4_26 : 32|16@1+ (1,-20000) [-20000|45535] "A"  PC
 SG_ M2P_PermitMaxDisCharge_I_B4_26 : 48|16@1+ (1,-20000) [-20000|45535] "A"  PC

BO_ 2334518955 M2P_SUMDATA30__27: 8 MBMU
 SG_ M2P_Measure_Vol_B4_27 : 0|16@1+ (0.1,0) [0|6553.5] "V"  PC,SBMU
 SG_ M2P_Current_B4_27 : 16|16@1+ (1,-20000) [-20000|45535] "A"  PC,SBMU
 SG_ M2P_PermitMaxCharge_I_B4_27 : 32|16@1+ (1,-20000) [-20000|45535] "A"  PC
 SG_ M2P_PermitMaxDisCharge_I_B4_27 : 48|16@1+ (1,-20000) [-20000|45535] "A"  PC

BO_ 2334518956 M2P_SUMDATA30__28: 8 MBMU
 SG_ M2P_Measure_Vol_B4_28 : 0|16@1+ (0.1,0) [0|6553.5] "V"  PC,SBMU
 SG_ M2P_Current_B4_28 : 16|16@1+ (1,-20000) [-20000|45535] "A"  PC,SBMU
 SG_ M2P_PermitMaxCharge_I_B4_28 : 32|16@1+ (1,-20000) [-20000|45535] "A"  PC
 SG_ M2P_PermitMaxDisCharge_I_B4_28 : 48|16@1+ (1,-20000) [-20000|45535] "A"  PC

BO_ 2334518957 M2P_SUMDATA30__29: 8 MBMU
 SG_ M2P_Measure_Vol_B4_29 : 0|16@1+ (0.1,0) [0|6553.5] "V"  PC,SBMU
 SG_ M2P_Current_B4_29 : 16|16@1+ (1,-20000) [-20000|45535] "A"  PC,SBMU
 SG_ M2P_PermitMaxCharge_I_B4_29 : 32|16@1+ (1,-20000) [-20000|45535] "A"  PC
 SG_ M2P_PermitMaxDisCharge_I_B4_29 : 48|16@1+ (1,-20000) [-20000|45535] "A"  PC

BO_ 2334518958 M2P_SUMDATA30__30: 8 MBMU
 SG_ M2P_Measure_Vol_B4_30 : 0|16@1+ (0.1,0) [0|6553.5] "V"  PC,SBMU
 SG_ M2P_Current_B4_30 : 16|16@1+ (1,-20000) [-20000|45535] "A"  PC,SBMU
 SG_ M2P_PermitMaxCharge_I_B4_30 : 32|16@1+ (1,-20000) [-20000|45535] "A"  PC
 SG_ M2P_PermitMaxDisCharge_I_B4_30 : 48|16@1+ (1,-20000) [-20000|45535] "A"  PC

BO_ 2334518959 M2P_SUMDATA30__31: 8 MBMU
 SG_ M2P_Measure_Vol_B4_31 : 0|16@1+ (0.1,0) [0|6553.5] "V"  PC,SBMU
 SG_ M2P_Current_B4_31 : 16|16@1+ (1,-20000) [-20000|45535] "A"  PC,SBMU
 SG_ M2P_PermitMaxCharge_I_B4_31 : 32|16@1+ (1,-20000) [-20000|45535] "A"  PC
 SG_ M2P_PermitMaxDisCharge_I_B4_31 : 48|16@1+ (1,-20000) [-20000|45535] "A"  PC

BO_ 2334584465 M2P_SUMDATA31__01: 8 MBMU
 SG_ M2P_PermitMaxVolt_B4_01 : 0|16@1+ (0.1,0) [0|6553.5] "V"  PC
 SG_ M2P_PermitMinVolt_B4_01 : 16|16@1+ (0.1,0) [0|6553.5] "V"  PC
 SG_ M2P_PermitMaxPow_Chg_B4_01 : 32|16@1+ (1,-20000) [-20000|45535] "Kw"  PC
 SG_ M2P_PermitMaxPow_DisChg_B4_01 : 48|16@1+ (1,-20000) [-20000|45535] "Kw"  PC

BO_ 2334584466 M2P_SUMDATA31__02: 8 MBMU
 SG_ M2P_PermitMaxVolt_B4_02 : 0|16@1+ (0.1,0) [0|6553.5] "V"  PC
 SG_ M2P_PermitMinVolt_B4_02 : 16|16@1+ (0.1,0) [0|6553.5] "V"  PC
 SG_ M2P_PermitMaxPow_Chg_B4_02 : 32|16@1+ (1,-20000) [-20000|45535] "Kw"  PC
 SG_ M2P_PermitMaxPow_DisChg_B4_02 : 48|16@1+ (1,-20000) [-20000|45535] "Kw"  PC

BO_ 2334584467 M2P_SUMDATA31__03: 8 MBMU
 SG_ M2P_PermitMaxVolt_B4_03 : 0|16@1+ (0.1,0) [0|6553.5] "V"  PC
 SG_ M2P_PermitMinVolt_B4_03 : 16|16@1+ (0.1,0) [0|6553.5] "V"  PC
 SG_ M2P_PermitMaxPow_Chg_B4_03 : 32|16@1+ (1,-20000) [-20000|45535] "Kw"  PC
 SG_ M2P_PermitMaxPow_DisChg_B4_03 : 48|16@1+ (1,-20000) [-20000|45535] "Kw"  PC

BO_ 2334584468 M2P_SUMDATA31__04: 8 MBMU
 SG_ M2P_PermitMaxVolt_B4_04 : 0|16@1+ (0.1,0) [0|6553.5] "V"  PC
 SG_ M2P_PermitMinVolt_B4_04 : 16|16@1+ (0.1,0) [0|6553.5] "V"  PC
 SG_ M2P_PermitMaxPow_Chg_B4_04 : 32|16@1+ (1,-20000) [-20000|45535] "Kw"  PC
 SG_ M2P_PermitMaxPow_DisChg_B4_04 : 48|16@1+ (1,-20000) [-20000|45535] "Kw"  PC

BO_ 2334584469 M2P_SUMDATA31__05: 8 MBMU
 SG_ M2P_PermitMaxVolt_B4_05 : 0|16@1+ (0.1,0) [0|6553.5] "V"  PC
 SG_ M2P_PermitMinVolt_B4_05 : 16|16@1+ (0.1,0) [0|6553.5] "V"  PC
 SG_ M2P_PermitMaxPow_Chg_B4_05 : 32|16@1+ (1,-20000) [-20000|45535] "Kw"  PC
 SG_ M2P_PermitMaxPow_DisChg_B4_05 : 48|16@1+ (1,-20000) [-20000|45535] "Kw"  PC

BO_ 2334584470 M2P_SUMDATA31__06: 8 MBMU
 SG_ M2P_PermitMaxVolt_B4_06 : 0|16@1+ (0.1,0) [0|6553.5] "V"  PC
 SG_ M2P_PermitMinVolt_B4_06 : 16|16@1+ (0.1,0) [0|6553.5] "V"  PC
 SG_ M2P_PermitMaxPow_Chg_B4_06 : 32|16@1+ (1,-20000) [-20000|45535] "Kw"  PC
 SG_ M2P_PermitMaxPow_DisChg_B4_06 : 48|16@1+ (1,-20000) [-20000|45535] "Kw"  PC

BO_ 2334584471 M2P_SUMDATA31__07: 8 MBMU
 SG_ M2P_PermitMaxVolt_B4_07 : 0|16@1+ (0.1,0) [0|6553.5] "V"  PC
 SG_ M2P_PermitMinVolt_B4_07 : 16|16@1+ (0.1,0) [0|6553.5] "V"  PC
 SG_ M2P_PermitMaxPow_Chg_B4_07 : 32|16@1+ (1,-20000) [-20000|45535] "Kw"  PC
 SG_ M2P_PermitMaxPow_DisChg_B4_07 : 48|16@1+ (1,-20000) [-20000|45535] "Kw"  PC

BO_ 2334584472 M2P_SUMDATA31__08: 8 MBMU
 SG_ M2P_PermitMaxVolt_B4_08 : 0|16@1+ (0.1,0) [0|6553.5] "V"  PC
 SG_ M2P_PermitMinVolt_B4_08 : 16|16@1+ (0.1,0) [0|6553.5] "V"  PC
 SG_ M2P_PermitMaxPow_Chg_B4_08 : 32|16@1+ (1,-20000) [-20000|45535] "Kw"  PC
 SG_ M2P_PermitMaxPow_DisChg_B4_08 : 48|16@1+ (1,-20000) [-20000|45535] "Kw"  PC

BO_ 2334584473 M2P_SUMDATA31__09: 8 MBMU
 SG_ M2P_PermitMaxVolt_B4_09 : 0|16@1+ (0.1,0) [0|6553.5] "V"  PC
 SG_ M2P_PermitMinVolt_B4_09 : 16|16@1+ (0.1,0) [0|6553.5] "V"  PC
 SG_ M2P_PermitMaxPow_Chg_B4_09 : 32|16@1+ (1,-20000) [-20000|45535] "Kw"  PC
 SG_ M2P_PermitMaxPow_DisChg_B4_09 : 48|16@1+ (1,-20000) [-20000|45535] "Kw"  PC

BO_ 2334584474 M2P_SUMDATA31__10: 8 MBMU
 SG_ M2P_PermitMaxVolt_B4_10 : 0|16@1+ (0.1,0) [0|6553.5] "V"  PC
 SG_ M2P_PermitMinVolt_B4_10 : 16|16@1+ (0.1,0) [0|6553.5] "V"  PC
 SG_ M2P_PermitMaxPow_Chg_B4_10 : 32|16@1+ (1,-20000) [-20000|45535] "Kw"  PC
 SG_ M2P_PermitMaxPow_DisChg_B4_10 : 48|16@1+ (1,-20000) [-20000|45535] "Kw"  PC

BO_ 2334584475 M2P_SUMDATA31__11: 8 MBMU
 SG_ M2P_PermitMaxVolt_B4_11 : 0|16@1+ (0.1,0) [0|6553.5] "V"  PC
 SG_ M2P_PermitMinVolt_B4_11 : 16|16@1+ (0.1,0) [0|6553.5] "V"  PC
 SG_ M2P_PermitMaxPow_Chg_B4_11 : 32|16@1+ (1,-20000) [-20000|45535] "Kw"  PC
 SG_ M2P_PermitMaxPow_DisChg_B4_11 : 48|16@1+ (1,-20000) [-20000|45535] "Kw"  PC

BO_ 2334584476 M2P_SUMDATA31__12: 8 MBMU
 SG_ M2P_PermitMaxVolt_B4_12 : 0|16@1+ (0.1,0) [0|6553.5] "V"  PC
 SG_ M2P_PermitMinVolt_B4_12 : 16|16@1+ (0.1,0) [0|6553.5] "V"  PC
 SG_ M2P_PermitMaxPow_Chg_B4_12 : 32|16@1+ (1,-20000) [-20000|45535] "Kw"  PC
 SG_ M2P_PermitMaxPow_DisChg_B4_12 : 48|16@1+ (1,-20000) [-20000|45535] "Kw"  PC

BO_ 2334584477 M2P_SUMDATA31__13: 8 MBMU
 SG_ M2P_PermitMaxVolt_B4_13 : 0|16@1+ (0.1,0) [0|6553.5] "V"  PC
 SG_ M2P_PermitMinVolt_B4_13 : 16|16@1+ (0.1,0) [0|6553.5] "V"  PC
 SG_ M2P_PermitMaxPow_Chg_B4_13 : 32|16@1+ (1,-20000) [-20000|45535] "Kw"  PC
 SG_ M2P_PermitMaxPow_DisChg_B4_13 : 48|16@1+ (1,-20000) [-20000|45535] "Kw"  PC

BO_ 2334584478 M2P_SUMDATA31__14: 8 MBMU
 SG_ M2P_PermitMaxVolt_B4_14 : 0|16@1+ (0.1,0) [0|6553.5] "V"  PC
 SG_ M2P_PermitMinVolt_B4_14 : 16|16@1+ (0.1,0) [0|6553.5] "V"  PC
 SG_ M2P_PermitMaxPow_Chg_B4_14 : 32|16@1+ (1,-20000) [-20000|45535] "Kw"  PC
 SG_ M2P_PermitMaxPow_DisChg_B4_14 : 48|16@1+ (1,-20000) [-20000|45535] "Kw"  PC

BO_ 2334584479 M2P_SUMDATA31__15: 8 MBMU
 SG_ M2P_PermitMaxVolt_B4_15 : 0|16@1+ (0.1,0) [0|6553.5] "V"  PC
 SG_ M2P_PermitMinVolt_B4_15 : 16|16@1+ (0.1,0) [0|6553.5] "V"  PC
 SG_ M2P_PermitMaxPow_Chg_B4_15 : 32|16@1+ (1,-20000) [-20000|45535] "Kw"  PC
 SG_ M2P_PermitMaxPow_DisChg_B4_15 : 48|16@1+ (1,-20000) [-20000|45535] "Kw"  PC

BO_ 2334584480 M2P_SUMDATA31__16: 8 MBMU
 SG_ M2P_PermitMaxVolt_B4_16 : 0|16@1+ (0.1,0) [0|6553.5] "V"  PC
 SG_ M2P_PermitMinVolt_B4_16 : 16|16@1+ (0.1,0) [0|6553.5] "V"  PC
 SG_ M2P_PermitMaxPow_Chg_B4_16 : 32|16@1+ (1,-20000) [-20000|45535] "Kw"  PC
 SG_ M2P_PermitMaxPow_DisChg_B4_16 : 48|16@1+ (1,-20000) [-20000|45535] "Kw"  PC

BO_ 2334584481 M2P_SUMDATA31__17: 8 MBMU
 SG_ M2P_PermitMaxVolt_B4_17 : 0|16@1+ (0.1,0) [0|6553.5] "V"  PC
 SG_ M2P_PermitMinVolt_B4_17 : 16|16@1+ (0.1,0) [0|6553.5] "V"  PC
 SG_ M2P_PermitMaxPow_Chg_B4_17 : 32|16@1+ (1,-20000) [-20000|45535] "Kw"  PC
 SG_ M2P_PermitMaxPow_DisChg_B4_17 : 48|16@1+ (1,-20000) [-20000|45535] "Kw"  PC

BO_ 2334584482 M2P_SUMDATA31__18: 8 MBMU
 SG_ M2P_PermitMaxVolt_B4_18 : 0|16@1+ (0.1,0) [0|6553.5] "V"  PC
 SG_ M2P_PermitMinVolt_B4_18 : 16|16@1+ (0.1,0) [0|6553.5] "V"  PC
 SG_ M2P_PermitMaxPow_Chg_B4_18 : 32|16@1+ (1,-20000) [-20000|45535] "Kw"  PC
 SG_ M2P_PermitMaxPow_DisChg_B4_18 : 48|16@1+ (1,-20000) [-20000|45535] "Kw"  PC

BO_ 2334584483 M2P_SUMDATA31__19: 8 MBMU
 SG_ M2P_PermitMaxVolt_B4_19 : 0|16@1+ (0.1,0) [0|6553.5] "V"  PC
 SG_ M2P_PermitMinVolt_B4_19 : 16|16@1+ (0.1,0) [0|6553.5] "V"  PC
 SG_ M2P_PermitMaxPow_Chg_B4_19 : 32|16@1+ (1,-20000) [-20000|45535] "Kw"  PC
 SG_ M2P_PermitMaxPow_DisChg_B4_19 : 48|16@1+ (1,-20000) [-20000|45535] "Kw"  PC

BO_ 2334584484 M2P_SUMDATA31__20: 8 MBMU
 SG_ M2P_PermitMaxVolt_B4_20 : 0|16@1+ (0.1,0) [0|6553.5] "V"  PC
 SG_ M2P_PermitMinVolt_B4_20 : 16|16@1+ (0.1,0) [0|6553.5] "V"  PC
 SG_ M2P_PermitMaxPow_Chg_B4_20 : 32|16@1+ (1,-20000) [-20000|45535] "Kw"  PC
 SG_ M2P_PermitMaxPow_DisChg_B4_20 : 48|16@1+ (1,-20000) [-20000|45535] "Kw"  PC

BO_ 2334584485 M2P_SUMDATA31__21: 8 MBMU
 SG_ M2P_PermitMaxVolt_B4_21 : 0|16@1+ (0.1,0) [0|6553.5] "V"  PC
 SG_ M2P_PermitMinVolt_B4_21 : 16|16@1+ (0.1,0) [0|6553.5] "V"  PC
 SG_ M2P_PermitMaxPow_Chg_B4_21 : 32|16@1+ (1,-20000) [-20000|45535] "Kw"  PC
 SG_ M2P_PermitMaxPow_DisChg_B4_21 : 48|16@1+ (1,-20000) [-20000|45535] "Kw"  PC

BO_ 2334584486 M2P_SUMDATA31__22: 8 MBMU
 SG_ M2P_PermitMaxVolt_B4_22 : 0|16@1+ (0.1,0) [0|6553.5] "V"  PC
 SG_ M2P_PermitMinVolt_B4_22 : 16|16@1+ (0.1,0) [0|6553.5] "V"  PC
 SG_ M2P_PermitMaxPow_Chg_B4_22 : 32|16@1+ (1,-20000) [-20000|45535] "Kw"  PC
 SG_ M2P_PermitMaxPow_DisChg_B4_22 : 48|16@1+ (1,-20000) [-20000|45535] "Kw"  PC

BO_ 2334584487 M2P_SUMDATA31__23: 8 MBMU
 SG_ M2P_PermitMaxVolt_B4_23 : 0|16@1+ (0.1,0) [0|6553.5] "V"  PC
 SG_ M2P_PermitMinVolt_B4_23 : 16|16@1+ (0.1,0) [0|6553.5] "V"  PC
 SG_ M2P_PermitMaxPow_Chg_B4_23 : 32|16@1+ (1,-20000) [-20000|45535] "Kw"  PC
 SG_ M2P_PermitMaxPow_DisChg_B4_23 : 48|16@1+ (1,-20000) [-20000|45535] "Kw"  PC

BO_ 2334584488 M2P_SUMDATA31__24: 8 MBMU
 SG_ M2P_PermitMaxVolt_B4_24 : 0|16@1+ (0.1,0) [0|6553.5] "V"  PC
 SG_ M2P_PermitMinVolt_B4_24 : 16|16@1+ (0.1,0) [0|6553.5] "V"  PC
 SG_ M2P_PermitMaxPow_Chg_B4_24 : 32|16@1+ (1,-20000) [-20000|45535] "Kw"  PC
 SG_ M2P_PermitMaxPow_DisChg_B4_24 : 48|16@1+ (1,-20000) [-20000|45535] "Kw"  PC

BO_ 2334584489 M2P_SUMDATA31__25: 8 MBMU
 SG_ M2P_PermitMaxVolt_B4_25 : 0|16@1+ (0.1,0) [0|6553.5] "V"  PC
 SG_ M2P_PermitMinVolt_B4_25 : 16|16@1+ (0.1,0) [0|6553.5] "V"  PC
 SG_ M2P_PermitMaxPow_Chg_B4_25 : 32|16@1+ (1,-20000) [-20000|45535] "Kw"  PC
 SG_ M2P_PermitMaxPow_DisChg_B4_25 : 48|16@1+ (1,-20000) [-20000|45535] "Kw"  PC

BO_ 2334584490 M2P_SUMDATA31__26: 8 MBMU
 SG_ M2P_PermitMaxVolt_B4_26 : 0|16@1+ (0.1,0) [0|6553.5] "V"  PC
 SG_ M2P_PermitMinVolt_B4_26 : 16|16@1+ (0.1,0) [0|6553.5] "V"  PC
 SG_ M2P_PermitMaxPow_Chg_B4_26 : 32|16@1+ (1,-20000) [-20000|45535] "Kw"  PC
 SG_ M2P_PermitMaxPow_DisChg_B4_26 : 48|16@1+ (1,-20000) [-20000|45535] "Kw"  PC

BO_ 2334584491 M2P_SUMDATA31__27: 8 MBMU
 SG_ M2P_PermitMaxVolt_B4_27 : 0|16@1+ (0.1,0) [0|6553.5] "V"  PC
 SG_ M2P_PermitMinVolt_B4_27 : 16|16@1+ (0.1,0) [0|6553.5] "V"  PC
 SG_ M2P_PermitMaxPow_Chg_B4_27 : 32|16@1+ (1,-20000) [-20000|45535] "Kw"  PC
 SG_ M2P_PermitMaxPow_DisChg_B4_27 : 48|16@1+ (1,-20000) [-20000|45535] "Kw"  PC

BO_ 2334584492 M2P_SUMDATA31__28: 8 MBMU
 SG_ M2P_PermitMaxVolt_B4_28 : 0|16@1+ (0.1,0) [0|6553.5] "V"  PC
 SG_ M2P_PermitMinVolt_B4_28 : 16|16@1+ (0.1,0) [0|6553.5] "V"  PC
 SG_ M2P_PermitMaxPow_Chg_B4_28 : 32|16@1+ (1,-20000) [-20000|45535] "Kw"  PC
 SG_ M2P_PermitMaxPow_DisChg_B4_28 : 48|16@1+ (1,-20000) [-20000|45535] "Kw"  PC

BO_ 2334584493 M2P_SUMDATA31__29: 8 MBMU
 SG_ M2P_PermitMaxVolt_B4_29 : 0|16@1+ (0.1,0) [0|6553.5] "V"  PC
 SG_ M2P_PermitMinVolt_B4_29 : 16|16@1+ (0.1,0) [0|6553.5] "V"  PC
 SG_ M2P_PermitMaxPow_Chg_B4_29 : 32|16@1+ (1,-20000) [-20000|45535] "Kw"  PC
 SG_ M2P_PermitMaxPow_DisChg_B4_29 : 48|16@1+ (1,-20000) [-20000|45535] "Kw"  PC

BO_ 2334584494 M2P_SUMDATA31__30: 8 MBMU
 SG_ M2P_PermitMaxVolt_B4_30 : 0|16@1+ (0.1,0) [0|6553.5] "V"  PC
 SG_ M2P_PermitMinVolt_B4_30 : 16|16@1+ (0.1,0) [0|6553.5] "V"  PC
 SG_ M2P_PermitMaxPow_Chg_B4_30 : 32|16@1+ (1,-20000) [-20000|45535] "Kw"  PC
 SG_ M2P_PermitMaxPow_DisChg_B4_30 : 48|16@1+ (1,-20000) [-20000|45535] "Kw"  PC

BO_ 2334584495 M2P_SUMDATA31__31: 8 MBMU
 SG_ M2P_PermitMaxVolt_B4_31 : 0|16@1+ (0.1,0) [0|6553.5] "V"  PC
 SG_ M2P_PermitMinVolt_B4_31 : 16|16@1+ (0.1,0) [0|6553.5] "V"  PC
 SG_ M2P_PermitMaxPow_Chg_B4_31 : 32|16@1+ (1,-20000) [-20000|45535] "Kw"  PC
 SG_ M2P_PermitMaxPow_DisChg_B4_31 : 48|16@1+ (1,-20000) [-20000|45535] "Kw"  PC

BO_ 2334650001 M2P_SUMDATA32__01: 8 MBMU
 SG_ M2P_Power_B4_01 : 0|16@1+ (1,-20000) [-20000|45535] "Kw"  PC
 SG_ M2P_SysremEngy_Chg_B4_01 : 16|16@1+ (1,0) [0|65535] "Kwh"  PC
 SG_ M2P_SysremEngy_DisChg_B4_01 : 32|16@1+ (1,0) [0|65535] "Kwh"  PC
 SG_ M2P_SysMaxVolt_B4_01 : 48|16@1+ (1,0) [0|65535] "mv"  PC

BO_ 2334650002 M2P_SUMDATA32__02: 8 MBMU
 SG_ M2P_Power_B4_02 : 0|16@1+ (1,-20000) [-20000|45535] "Kw"  PC
 SG_ M2P_SysremEngy_Chg_B4_02 : 16|16@1+ (1,0) [0|65535] "Kwh"  PC
 SG_ M2P_SysremEngy_DisChg_B4_02 : 32|16@1+ (1,0) [0|65535] "Kwh"  PC
 SG_ M2P_SysMaxVolt_B4_02 : 48|16@1+ (1,0) [0|65535] "mv"  PC

BO_ 2334650003 M2P_SUMDATA32__03: 8 MBMU
 SG_ M2P_Power_B4_03 : 0|16@1+ (1,-20000) [-20000|45535] "Kw"  PC
 SG_ M2P_SysremEngy_Chg_B4_03 : 16|16@1+ (1,0) [0|65535] "Kwh"  PC
 SG_ M2P_SysremEngy_DisChg_B4_03 : 32|16@1+ (1,0) [0|65535] "Kwh"  PC
 SG_ M2P_SysMaxVolt_B4_03 : 48|16@1+ (1,0) [0|65535] "mv"  PC

BO_ 2334650004 M2P_SUMDATA32__04: 8 MBMU
 SG_ M2P_Power_B4_04 : 0|16@1+ (1,-20000) [-20000|45535] "Kw"  PC
 SG_ M2P_SysremEngy_Chg_B4_04 : 16|16@1+ (1,0) [0|65535] "Kwh"  PC
 SG_ M2P_SysremEngy_DisChg_B4_04 : 32|16@1+ (1,0) [0|65535] "Kwh"  PC
 SG_ M2P_SysMaxVolt_B4_04 : 48|16@1+ (1,0) [0|65535] "mv"  PC

BO_ 2334650005 M2P_SUMDATA32__05: 8 MBMU
 SG_ M2P_Power_B4_05 : 0|16@1+ (1,-20000) [-20000|45535] "Kw"  PC
 SG_ M2P_SysremEngy_Chg_B4_05 : 16|16@1+ (1,0) [0|65535] "Kwh"  PC
 SG_ M2P_SysremEngy_DisChg_B4_05 : 32|16@1+ (1,0) [0|65535] "Kwh"  PC
 SG_ M2P_SysMaxVolt_B4_05 : 48|16@1+ (1,0) [0|65535] "mv"  PC

BO_ 2334650006 M2P_SUMDATA32__06: 8 MBMU
 SG_ M2P_Power_B4_06 : 0|16@1+ (1,-20000) [-20000|45535] "Kw"  PC
 SG_ M2P_SysremEngy_Chg_B4_06 : 16|16@1+ (1,0) [0|65535] "Kwh"  PC
 SG_ M2P_SysremEngy_DisChg_B4_06 : 32|16@1+ (1,0) [0|65535] "Kwh"  PC
 SG_ M2P_SysMaxVolt_B4_06 : 48|16@1+ (1,0) [0|65535] "mv"  PC

BO_ 2334650007 M2P_SUMDATA32__07: 8 MBMU
 SG_ M2P_Power_B4_07 : 0|16@1+ (1,-20000) [-20000|45535] "Kw"  PC
 SG_ M2P_SysremEngy_Chg_B4_07 : 16|16@1+ (1,0) [0|65535] "Kwh"  PC
 SG_ M2P_SysremEngy_DisChg_B4_07 : 32|16@1+ (1,0) [0|65535] "Kwh"  PC
 SG_ M2P_SysMaxVolt_B4_07 : 48|16@1+ (1,0) [0|65535] "mv"  PC

BO_ 2334650008 M2P_SUMDATA32__08: 8 MBMU
 SG_ M2P_Power_B4_08 : 0|16@1+ (1,-20000) [-20000|45535] "Kw"  PC
 SG_ M2P_SysremEngy_Chg_B4_08 : 16|16@1+ (1,0) [0|65535] "Kwh"  PC
 SG_ M2P_SysremEngy_DisChg_B4_08 : 32|16@1+ (1,0) [0|65535] "Kwh"  PC
 SG_ M2P_SysMaxVolt_B4_08 : 48|16@1+ (1,0) [0|65535] "mv"  PC

BO_ 2334650009 M2P_SUMDATA32__09: 8 MBMU
 SG_ M2P_Power_B4_09 : 0|16@1+ (1,-20000) [-20000|45535] "Kw"  PC
 SG_ M2P_SysremEngy_Chg_B4_09 : 16|16@1+ (1,0) [0|65535] "Kwh"  PC
 SG_ M2P_SysremEngy_DisChg_B4_09 : 32|16@1+ (1,0) [0|65535] "Kwh"  PC
 SG_ M2P_SysMaxVolt_B4_09 : 48|16@1+ (1,0) [0|65535] "mv"  PC

BO_ 2334650010 M2P_SUMDATA32__10: 8 MBMU
 SG_ M2P_Power_B4_10 : 0|16@1+ (1,-20000) [-20000|45535] "Kw"  PC
 SG_ M2P_SysremEngy_Chg_B4_10 : 16|16@1+ (1,0) [0|65535] "Kwh"  PC
 SG_ M2P_SysremEngy_DisChg_B4_10 : 32|16@1+ (1,0) [0|65535] "Kwh"  PC
 SG_ M2P_SysMaxVolt_B4_10 : 48|16@1+ (1,0) [0|65535] "mv"  PC

BO_ 2334650011 M2P_SUMDATA32__11: 8 MBMU
 SG_ M2P_Power_B4_11 : 0|16@1+ (1,-20000) [-20000|45535] "Kw"  PC
 SG_ M2P_SysremEngy_Chg_B4_11 : 16|16@1+ (1,0) [0|65535] "Kwh"  PC
 SG_ M2P_SysremEngy_DisChg_B4_11 : 32|16@1+ (1,0) [0|65535] "Kwh"  PC
 SG_ M2P_SysMaxVolt_B4_11 : 48|16@1+ (1,0) [0|65535] "mv"  PC

BO_ 2334650012 M2P_SUMDATA32__12: 8 MBMU
 SG_ M2P_Power_B4_12 : 0|16@1+ (1,-20000) [-20000|45535] "Kw"  PC
 SG_ M2P_SysremEngy_Chg_B4_12 : 16|16@1+ (1,0) [0|65535] "Kwh"  PC
 SG_ M2P_SysremEngy_DisChg_B4_12 : 32|16@1+ (1,0) [0|65535] "Kwh"  PC
 SG_ M2P_SysMaxVolt_B4_12 : 48|16@1+ (1,0) [0|65535] "mv"  PC

BO_ 2334650013 M2P_SUMDATA32__13: 8 MBMU
 SG_ M2P_Power_B4_13 : 0|16@1+ (1,-20000) [-20000|45535] "Kw"  PC
 SG_ M2P_SysremEngy_Chg_B4_13 : 16|16@1+ (1,0) [0|65535] "Kwh"  PC
 SG_ M2P_SysremEngy_DisChg_B4_13 : 32|16@1+ (1,0) [0|65535] "Kwh"  PC
 SG_ M2P_SysMaxVolt_B4_13 : 48|16@1+ (1,0) [0|65535] "mv"  PC

BO_ 2334650014 M2P_SUMDATA32__14: 8 MBMU
 SG_ M2P_Power_B4_14 : 0|16@1+ (1,-20000) [-20000|45535] "Kw"  PC
 SG_ M2P_SysremEngy_Chg_B4_14 : 16|16@1+ (1,0) [0|65535] "Kwh"  PC
 SG_ M2P_SysremEngy_DisChg_B4_14 : 32|16@1+ (1,0) [0|65535] "Kwh"  PC
 SG_ M2P_SysMaxVolt_B4_14 : 48|16@1+ (1,0) [0|65535] "mv"  PC

BO_ 2334650015 M2P_SUMDATA32__15: 8 MBMU
 SG_ M2P_Power_B4_15 : 0|16@1+ (1,-20000) [-20000|45535] "Kw"  PC
 SG_ M2P_SysremEngy_Chg_B4_15 : 16|16@1+ (1,0) [0|65535] "Kwh"  PC
 SG_ M2P_SysremEngy_DisChg_B4_15 : 32|16@1+ (1,0) [0|65535] "Kwh"  PC
 SG_ M2P_SysMaxVolt_B4_15 : 48|16@1+ (1,0) [0|65535] "mv"  PC

BO_ 2334650016 M2P_SUMDATA32__16: 8 MBMU
 SG_ M2P_Power_B4_16 : 0|16@1+ (1,-20000) [-20000|45535] "Kw"  PC
 SG_ M2P_SysremEngy_Chg_B4_16 : 16|16@1+ (1,0) [0|65535] "Kwh"  PC
 SG_ M2P_SysremEngy_DisChg_B4_16 : 32|16@1+ (1,0) [0|65535] "Kwh"  PC
 SG_ M2P_SysMaxVolt_B4_16 : 48|16@1+ (1,0) [0|65535] "mv"  PC

BO_ 2334650017 M2P_SUMDATA32__17: 8 MBMU
 SG_ M2P_Power_B4_17 : 0|16@1+ (1,-20000) [-20000|45535] "Kw"  PC
 SG_ M2P_SysremEngy_Chg_B4_17 : 16|16@1+ (1,0) [0|65535] "Kwh"  PC
 SG_ M2P_SysremEngy_DisChg_B4_17 : 32|16@1+ (1,0) [0|65535] "Kwh"  PC
 SG_ M2P_SysMaxVolt_B4_17 : 48|16@1+ (1,0) [0|65535] "mv"  PC

BO_ 2334650018 M2P_SUMDATA32__18: 8 MBMU
 SG_ M2P_Power_B4_18 : 0|16@1+ (1,-20000) [-20000|45535] "Kw"  PC
 SG_ M2P_SysremEngy_Chg_B4_18 : 16|16@1+ (1,0) [0|65535] "Kwh"  PC
 SG_ M2P_SysremEngy_DisChg_B4_18 : 32|16@1+ (1,0) [0|65535] "Kwh"  PC
 SG_ M2P_SysMaxVolt_B4_18 : 48|16@1+ (1,0) [0|65535] "mv"  PC

BO_ 2334650019 M2P_SUMDATA32__19: 8 MBMU
 SG_ M2P_Power_B4_19 : 0|16@1+ (1,-20000) [-20000|45535] "Kw"  PC
 SG_ M2P_SysremEngy_Chg_B4_19 : 16|16@1+ (1,0) [0|65535] "Kwh"  PC
 SG_ M2P_SysremEngy_DisChg_B4_19 : 32|16@1+ (1,0) [0|65535] "Kwh"  PC
 SG_ M2P_SysMaxVolt_B4_19 : 48|16@1+ (1,0) [0|65535] "mv"  PC

BO_ 2334650020 M2P_SUMDATA32__20: 8 MBMU
 SG_ M2P_Power_B4_20 : 0|16@1+ (1,-20000) [-20000|45535] "Kw"  PC
 SG_ M2P_SysremEngy_Chg_B4_20 : 16|16@1+ (1,0) [0|65535] "Kwh"  PC
 SG_ M2P_SysremEngy_DisChg_B4_20 : 32|16@1+ (1,0) [0|65535] "Kwh"  PC
 SG_ M2P_SysMaxVolt_B4_20 : 48|16@1+ (1,0) [0|65535] "mv"  PC

BO_ 2334650021 M2P_SUMDATA32__21: 8 MBMU
 SG_ M2P_Power_B4_21 : 0|16@1+ (1,-20000) [-20000|45535] "Kw"  PC
 SG_ M2P_SysremEngy_Chg_B4_21 : 16|16@1+ (1,0) [0|65535] "Kwh"  PC
 SG_ M2P_SysremEngy_DisChg_B4_21 : 32|16@1+ (1,0) [0|65535] "Kwh"  PC
 SG_ M2P_SysMaxVolt_B4_21 : 48|16@1+ (1,0) [0|65535] "mv"  PC

BO_ 2334650022 M2P_SUMDATA32__22: 8 MBMU
 SG_ M2P_Power_B4_22 : 0|16@1+ (1,-20000) [-20000|45535] "Kw"  PC
 SG_ M2P_SysremEngy_Chg_B4_22 : 16|16@1+ (1,0) [0|65535] "Kwh"  PC
 SG_ M2P_SysremEngy_DisChg_B4_22 : 32|16@1+ (1,0) [0|65535] "Kwh"  PC
 SG_ M2P_SysMaxVolt_B4_22 : 48|16@1+ (1,0) [0|65535] "mv"  PC

BO_ 2334650023 M2P_SUMDATA32__23: 8 MBMU
 SG_ M2P_Power_B4_23 : 0|16@1+ (1,-20000) [-20000|45535] "Kw"  PC
 SG_ M2P_SysremEngy_Chg_B4_23 : 16|16@1+ (1,0) [0|65535] "Kwh"  PC
 SG_ M2P_SysremEngy_DisChg_B4_23 : 32|16@1+ (1,0) [0|65535] "Kwh"  PC
 SG_ M2P_SysMaxVolt_B4_23 : 48|16@1+ (1,0) [0|65535] "mv"  PC

BO_ 2334650024 M2P_SUMDATA32__24: 8 MBMU
 SG_ M2P_Power_B4_24 : 0|16@1+ (1,-20000) [-20000|45535] "Kw"  PC
 SG_ M2P_SysremEngy_Chg_B4_24 : 16|16@1+ (1,0) [0|65535] "Kwh"  PC
 SG_ M2P_SysremEngy_DisChg_B4_24 : 32|16@1+ (1,0) [0|65535] "Kwh"  PC
 SG_ M2P_SysMaxVolt_B4_24 : 48|16@1+ (1,0) [0|65535] "mv"  PC

BO_ 2334650025 M2P_SUMDATA32__25: 8 MBMU
 SG_ M2P_Power_B4_25 : 0|16@1+ (1,-20000) [-20000|45535] "Kw"  PC
 SG_ M2P_SysremEngy_Chg_B4_25 : 16|16@1+ (1,0) [0|65535] "Kwh"  PC
 SG_ M2P_SysremEngy_DisChg_B4_25 : 32|16@1+ (1,0) [0|65535] "Kwh"  PC
 SG_ M2P_SysMaxVolt_B4_25 : 48|16@1+ (1,0) [0|65535] "mv"  PC

BO_ 2334650026 M2P_SUMDATA32__26: 8 MBMU
 SG_ M2P_Power_B4_26 : 0|16@1+ (1,-20000) [-20000|45535] "Kw"  PC
 SG_ M2P_SysremEngy_Chg_B4_26 : 16|16@1+ (1,0) [0|65535] "Kwh"  PC
 SG_ M2P_SysremEngy_DisChg_B4_26 : 32|16@1+ (1,0) [0|65535] "Kwh"  PC
 SG_ M2P_SysMaxVolt_B4_26 : 48|16@1+ (1,0) [0|65535] "mv"  PC

BO_ 2334650027 M2P_SUMDATA32__27: 8 MBMU
 SG_ M2P_Power_B4_27 : 0|16@1+ (1,-20000) [-20000|45535] "Kw"  PC
 SG_ M2P_SysremEngy_Chg_B4_27 : 16|16@1+ (1,0) [0|65535] "Kwh"  PC
 SG_ M2P_SysremEngy_DisChg_B4_27 : 32|16@1+ (1,0) [0|65535] "Kwh"  PC
 SG_ M2P_SysMaxVolt_B4_27 : 48|16@1+ (1,0) [0|65535] "mv"  PC

BO_ 2334650028 M2P_SUMDATA32__28: 8 MBMU
 SG_ M2P_Power_B4_28 : 0|16@1+ (1,-20000) [-20000|45535] "Kw"  PC
 SG_ M2P_SysremEngy_Chg_B4_28 : 16|16@1+ (1,0) [0|65535] "Kwh"  PC
 SG_ M2P_SysremEngy_DisChg_B4_28 : 32|16@1+ (1,0) [0|65535] "Kwh"  PC
 SG_ M2P_SysMaxVolt_B4_28 : 48|16@1+ (1,0) [0|65535] "mv"  PC

BO_ 2334650029 M2P_SUMDATA32__29: 8 MBMU
 SG_ M2P_Power_B4_29 : 0|16@1+ (1,-20000) [-20000|45535] "Kw"  PC
 SG_ M2P_SysremEngy_Chg_B4_29 : 16|16@1+ (1,0) [0|65535] "Kwh"  PC
 SG_ M2P_SysremEngy_DisChg_B4_29 : 32|16@1+ (1,0) [0|65535] "Kwh"  PC
 SG_ M2P_SysMaxVolt_B4_29 : 48|16@1+ (1,0) [0|65535] "mv"  PC

BO_ 2334650030 M2P_SUMDATA32__30: 8 MBMU
 SG_ M2P_Power_B4_30 : 0|16@1+ (1,-20000) [-20000|45535] "Kw"  PC
 SG_ M2P_SysremEngy_Chg_B4_30 : 16|16@1+ (1,0) [0|65535] "Kwh"  PC
 SG_ M2P_SysremEngy_DisChg_B4_30 : 32|16@1+ (1,0) [0|65535] "Kwh"  PC
 SG_ M2P_SysMaxVolt_B4_30 : 48|16@1+ (1,0) [0|65535] "mv"  PC

BO_ 2334650031 M2P_SUMDATA32__31: 8 MBMU
 SG_ M2P_Power_B4_31 : 0|16@1+ (1,-20000) [-20000|45535] "Kw"  PC
 SG_ M2P_SysremEngy_Chg_B4_31 : 16|16@1+ (1,0) [0|65535] "Kwh"  PC
 SG_ M2P_SysremEngy_DisChg_B4_31 : 32|16@1+ (1,0) [0|65535] "Kwh"  PC
 SG_ M2P_SysMaxVolt_B4_31 : 48|16@1+ (1,0) [0|65535] "mv"  PC

BO_ 2334715537 M2P_SUMDATA33__01: 8 MBMU
 SG_ M2P_SysMinVolt_B4_01 : 0|16@1+ (1,0) [0|65535] "mv"  PC
 SG_ M2P_SysAvgVolt_B4_01 : 16|16@1+ (1,0) [0|65535] "mv"  PC
 SG_ M2P_BMS_Status_B4 : 32|3@1+ (1,0) [0|7] ""  PC
 SG_ M2P_SOC_B4 : 35|10@1+ (0.1,0) [0|102.3] "%"  PC
 SG_ M2P_SOH_B4 : 45|8@1+ (1,0) [0|255] "%"  PC
 SG_ Reserved_01 : 53|11@1+ (1,0) [0|2047] ""  PC

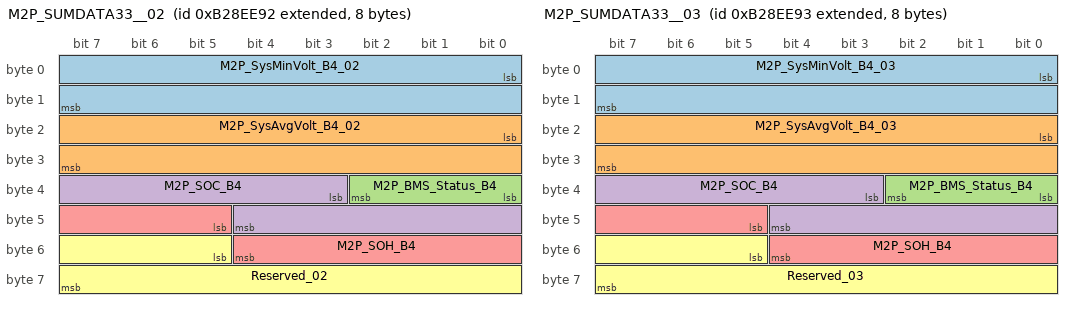
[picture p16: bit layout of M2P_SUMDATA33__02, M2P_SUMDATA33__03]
BO_ 2334715538 M2P_SUMDATA33__02: 8 MBMU
 SG_ M2P_SysMinVolt_B4_02 : 0|16@1+ (1,0) [0|65535] "mv"  PC
 SG_ M2P_SysAvgVolt_B4_02 : 16|16@1+ (1,0) [0|65535] "mv"  PC
 SG_ M2P_BMS_Status_B4 : 32|3@1+ (1,0) [0|7] ""  PC
 SG_ M2P_SOC_B4 : 35|10@1+ (0.1,0) [0|102.3] "%"  PC
 SG_ M2P_SOH_B4 : 45|8@1+ (1,0) [0|255] "%"  PC
 SG_ Reserved_02 : 53|11@1+ (1,0) [0|2047] ""  PC

BO_ 2334715539 M2P_SUMDATA33__03: 8 MBMU
 SG_ M2P_SysMinVolt_B4_03 : 0|16@1+ (1,0) [0|65535] "mv"  PC
 SG_ M2P_SysAvgVolt_B4_03 : 16|16@1+ (1,0) [0|65535] "mv"  PC
 SG_ M2P_BMS_Status_B4 : 32|3@1+ (1,0) [0|7] ""  PC
 SG_ M2P_SOC_B4 : 35|10@1+ (0.1,0) [0|102.3] "%"  PC
 SG_ M2P_SOH_B4 : 45|8@1+ (1,0) [0|255] "%"  PC
 SG_ Reserved_03 : 53|11@1+ (1,0) [0|2047] ""  PC

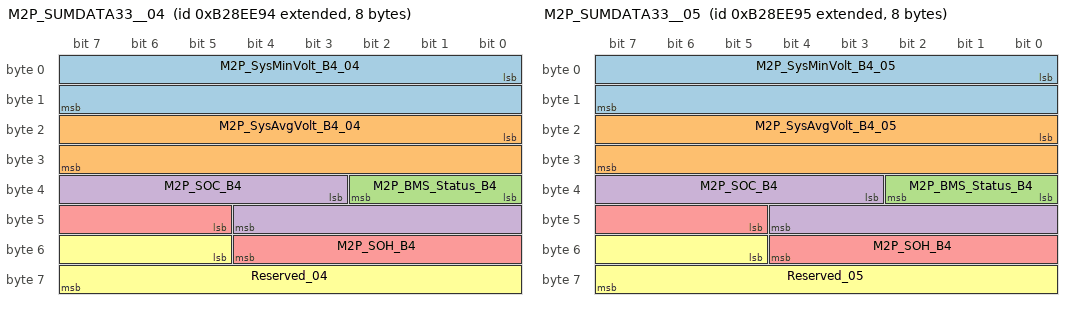
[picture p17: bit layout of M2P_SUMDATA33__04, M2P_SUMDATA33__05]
BO_ 2334715540 M2P_SUMDATA33__04: 8 MBMU
 SG_ M2P_SysMinVolt_B4_04 : 0|16@1+ (1,0) [0|65535] "mv"  PC
 SG_ M2P_SysAvgVolt_B4_04 : 16|16@1+ (1,0) [0|65535] "mv"  PC
 SG_ M2P_BMS_Status_B4 : 32|3@1+ (1,0) [0|7] ""  PC
 SG_ M2P_SOC_B4 : 35|10@1+ (0.1,0) [0|102.3] "%"  PC
 SG_ M2P_SOH_B4 : 45|8@1+ (1,0) [0|255] "%"  PC
 SG_ Reserved_04 : 53|11@1+ (1,0) [0|2047] ""  PC

BO_ 2334715541 M2P_SUMDATA33__05: 8 MBMU
 SG_ M2P_SysMinVolt_B4_05 : 0|16@1+ (1,0) [0|65535] "mv"  PC
 SG_ M2P_SysAvgVolt_B4_05 : 16|16@1+ (1,0) [0|65535] "mv"  PC
 SG_ M2P_BMS_Status_B4 : 32|3@1+ (1,0) [0|7] ""  PC
 SG_ M2P_SOC_B4 : 35|10@1+ (0.1,0) [0|102.3] "%"  PC
 SG_ M2P_SOH_B4 : 45|8@1+ (1,0) [0|255] "%"  PC
 SG_ Reserved_05 : 53|11@1+ (1,0) [0|2047] ""  PC

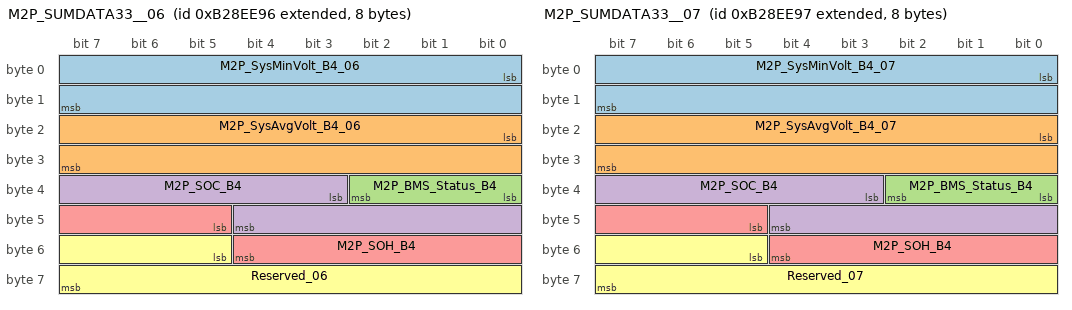
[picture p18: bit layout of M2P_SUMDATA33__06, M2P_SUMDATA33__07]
BO_ 2334715542 M2P_SUMDATA33__06: 8 MBMU
 SG_ M2P_SysMinVolt_B4_06 : 0|16@1+ (1,0) [0|65535] "mv"  PC
 SG_ M2P_SysAvgVolt_B4_06 : 16|16@1+ (1,0) [0|65535] "mv"  PC
 SG_ M2P_BMS_Status_B4 : 32|3@1+ (1,0) [0|7] ""  PC
 SG_ M2P_SOC_B4 : 35|10@1+ (0.1,0) [0|102.3] "%"  PC
 SG_ M2P_SOH_B4 : 45|8@1+ (1,0) [0|255] "%"  PC
 SG_ Reserved_06 : 53|11@1+ (1,0) [0|2047] ""  PC

BO_ 2334715543 M2P_SUMDATA33__07: 8 MBMU
 SG_ M2P_SysMinVolt_B4_07 : 0|16@1+ (1,0) [0|65535] "mv"  PC
 SG_ M2P_SysAvgVolt_B4_07 : 16|16@1+ (1,0) [0|65535] "mv"  PC
 SG_ M2P_BMS_Status_B4 : 32|3@1+ (1,0) [0|7] ""  PC
 SG_ M2P_SOC_B4 : 35|10@1+ (0.1,0) [0|102.3] "%"  PC
 SG_ M2P_SOH_B4 : 45|8@1+ (1,0) [0|255] "%"  PC
 SG_ Reserved_07 : 53|11@1+ (1,0) [0|2047] ""  PC

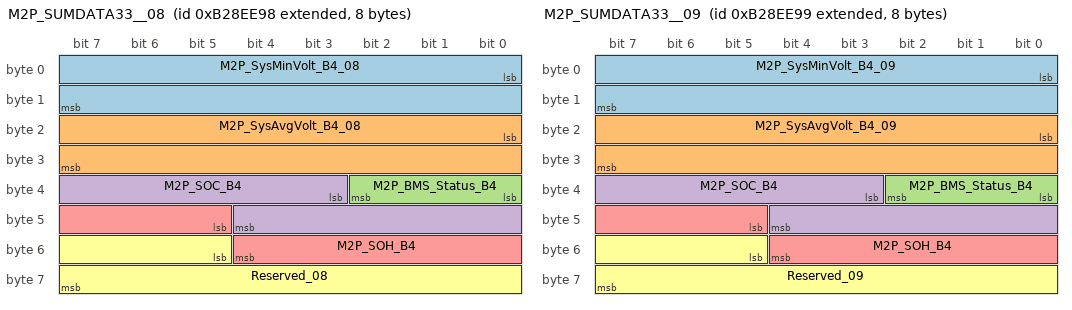
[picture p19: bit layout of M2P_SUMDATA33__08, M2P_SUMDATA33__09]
BO_ 2334715544 M2P_SUMDATA33__08: 8 MBMU
 SG_ M2P_SysMinVolt_B4_08 : 0|16@1+ (1,0) [0|65535] "mv"  PC
 SG_ M2P_SysAvgVolt_B4_08 : 16|16@1+ (1,0) [0|65535] "mv"  PC
 SG_ M2P_BMS_Status_B4 : 32|3@1+ (1,0) [0|7] ""  PC
 SG_ M2P_SOC_B4 : 35|10@1+ (0.1,0) [0|102.3] "%"  PC
 SG_ M2P_SOH_B4 : 45|8@1+ (1,0) [0|255] "%"  PC
 SG_ Reserved_08 : 53|11@1+ (1,0) [0|2047] ""  PC

BO_ 2334715545 M2P_SUMDATA33__09: 8 MBMU
 SG_ M2P_SysMinVolt_B4_09 : 0|16@1+ (1,0) [0|65535] "mv"  PC
 SG_ M2P_SysAvgVolt_B4_09 : 16|16@1+ (1,0) [0|65535] "mv"  PC
 SG_ M2P_BMS_Status_B4 : 32|3@1+ (1,0) [0|7] ""  PC
 SG_ M2P_SOC_B4 : 35|10@1+ (0.1,0) [0|102.3] "%"  PC
 SG_ M2P_SOH_B4 : 45|8@1+ (1,0) [0|255] "%"  PC
 SG_ Reserved_09 : 53|11@1+ (1,0) [0|2047] ""  PC

BO_ 2334715546 M2P_SUMDATA33__10: 8 MBMU
 SG_ M2P_SysMinVolt_B4_10 : 0|16@1+ (1,0) [0|65535] "mv"  PC
 SG_ M2P_SysAvgVolt_B4_10 : 16|16@1+ (1,0) [0|65535] "mv"  PC
 SG_ M2P_BMS_Status_B4 : 32|3@1+ (1,0) [0|7] ""  PC
 SG_ M2P_SOC_B4 : 35|10@1+ (0.1,0) [0|102.3] "%"  PC
 SG_ M2P_SOH_B4 : 45|8@1+ (1,0) [0|255] "%"  PC
 SG_ Reserved_10 : 53|11@1+ (1,0) [0|2047] ""  PC

BO_ 2334715547 M2P_SUMDATA33__11: 8 MBMU
 SG_ M2P_SysMinVolt_B4_11 : 0|16@1+ (1,0) [0|65535] "mv"  PC
 SG_ M2P_SysAvgVolt_B4_11 : 16|16@1+ (1,0) [0|65535] "mv"  PC
 SG_ M2P_BMS_Status_B4 : 32|3@1+ (1,0) [0|7] ""  PC
 SG_ M2P_SOC_B4 : 35|10@1+ (0.1,0) [0|102.3] "%"  PC
 SG_ M2P_SOH_B4 : 45|8@1+ (1,0) [0|255] "%"  PC
 SG_ Reserved_11 : 53|11@1+ (1,0) [0|2047] ""  PC

BO_ 2334715548 M2P_SUMDATA33__12: 8 MBMU
 SG_ M2P_SysMinVolt_B4_12 : 0|16@1+ (1,0) [0|65535] "mv"  PC
 SG_ M2P_SysAvgVolt_B4_12 : 16|16@1+ (1,0) [0|65535] "mv"  PC
 SG_ M2P_BMS_Status_B4 : 32|3@1+ (1,0) [0|7] ""  PC
 SG_ M2P_SOC_B4 : 35|10@1+ (0.1,0) [0|102.3] "%"  PC
 SG_ M2P_SOH_B4 : 45|8@1+ (1,0) [0|255] "%"  PC
 SG_ Reserved_12 : 53|11@1+ (1,0) [0|2047] ""  PC

BO_ 2334715549 M2P_SUMDATA33__13: 8 MBMU
 SG_ M2P_SysMinVolt_B4_13 : 0|16@1+ (1,0) [0|65535] "mv"  PC
 SG_ M2P_SysAvgVolt_B4_13 : 16|16@1+ (1,0) [0|65535] "mv"  PC
 SG_ M2P_BMS_Status_B4 : 32|3@1+ (1,0) [0|7] ""  PC
 SG_ M2P_SOC_B4 : 35|10@1+ (0.1,0) [0|102.3] "%"  PC
 SG_ M2P_SOH_B4 : 45|8@1+ (1,0) [0|255] "%"  PC
 SG_ Reserved_13 : 53|11@1+ (1,0) [0|2047] ""  PC

BO_ 2334715550 M2P_SUMDATA33__14: 8 MBMU
 SG_ M2P_SysMinVolt_B4_14 : 0|16@1+ (1,0) [0|65535] "mv"  PC
 SG_ M2P_SysAvgVolt_B4_14 : 16|16@1+ (1,0) [0|65535] "mv"  PC
 SG_ M2P_BMS_Status_B4 : 32|3@1+ (1,0) [0|7] ""  PC
 SG_ M2P_SOC_B4 : 35|10@1+ (0.1,0) [0|102.3] "%"  PC
 SG_ M2P_SOH_B4 : 45|8@1+ (1,0) [0|255] "%"  PC
 SG_ Reserved_14 : 53|11@1+ (1,0) [0|2047] ""  PC

BO_ 2334715551 M2P_SUMDATA33__15: 8 MBMU
 SG_ M2P_SysMinVolt_B4_15 : 0|16@1+ (1,0) [0|65535] "mv"  PC
 SG_ M2P_SysAvgVolt_B4_15 : 16|16@1+ (1,0) [0|65535] "mv"  PC
 SG_ M2P_BMS_Status_B4 : 32|3@1+ (1,0) [0|7] ""  PC
 SG_ M2P_SOC_B4 : 35|10@1+ (0.1,0) [0|102.3] "%"  PC
 SG_ M2P_SOH_B4 : 45|8@1+ (1,0) [0|255] "%"  PC
 SG_ Reserved_15 : 53|11@1+ (1,0) [0|2047] ""  PC

BO_ 2334715552 M2P_SUMDATA33__16: 8 MBMU
 SG_ M2P_SysMinVolt_B4_16 : 0|16@1+ (1,0) [0|65535] "mv"  PC
 SG_ M2P_SysAvgVolt_B4_16 : 16|16@1+ (1,0) [0|65535] "mv"  PC
 SG_ M2P_BMS_Status_B4 : 32|3@1+ (1,0) [0|7] ""  PC
 SG_ M2P_SOC_B4 : 35|10@1+ (0.1,0) [0|102.3] "%"  PC
 SG_ M2P_SOH_B4 : 45|8@1+ (1,0) [0|255] "%"  PC
 SG_ Reserved_16 : 53|11@1+ (1,0) [0|2047] ""  PC

BO_ 2334715553 M2P_SUMDATA33__17: 8 MBMU
 SG_ M2P_SysMinVolt_B4_17 : 0|16@1+ (1,0) [0|65535] "mv"  PC
 SG_ M2P_SysAvgVolt_B4_17 : 16|16@1+ (1,0) [0|65535] "mv"  PC
 SG_ M2P_BMS_Status_B4 : 32|3@1+ (1,0) [0|7] ""  PC
 SG_ M2P_SOC_B4 : 35|10@1+ (0.1,0) [0|102.3] "%"  PC
 SG_ M2P_SOH_B4 : 45|8@1+ (1,0) [0|255] "%"  PC
 SG_ Reserved_17 : 53|11@1+ (1,0) [0|2047] ""  PC

BO_ 2334715554 M2P_SUMDATA33__18: 8 MBMU
 SG_ M2P_SysMinVolt_B4_18 : 0|16@1+ (1,0) [0|65535] "mv"  PC
 SG_ M2P_SysAvgVolt_B4_18 : 16|16@1+ (1,0) [0|65535] "mv"  PC
 SG_ M2P_BMS_Status_B4 : 32|3@1+ (1,0) [0|7] ""  PC
 SG_ M2P_SOC_B4 : 35|10@1+ (0.1,0) [0|102.3] "%"  PC
 SG_ M2P_SOH_B4 : 45|8@1+ (1,0) [0|255] "%"  PC
 SG_ Reserved_18 : 53|11@1+ (1,0) [0|2047] ""  PC

BO_ 2334715555 M2P_SUMDATA33__19: 8 MBMU
 SG_ M2P_SysMinVolt_B4_19 : 0|16@1+ (1,0) [0|65535] "mv"  PC
 SG_ M2P_SysAvgVolt_B4_19 : 16|16@1+ (1,0) [0|65535] "mv"  PC
 SG_ M2P_BMS_Status_B4 : 32|3@1+ (1,0) [0|7] ""  PC
 SG_ M2P_SOC_B4 : 35|10@1+ (0.1,0) [0|102.3] "%"  PC
 SG_ M2P_SOH_B4 : 45|8@1+ (1,0) [0|255] "%"  PC
 SG_ Reserved_19 : 53|11@1+ (1,0) [0|2047] ""  PC

BO_ 2334715556 M2P_SUMDATA33__20: 8 MBMU
 SG_ M2P_SysMinVolt_B4_20 : 0|16@1+ (1,0) [0|65535] "mv"  PC
 SG_ M2P_SysAvgVolt_B4_20 : 16|16@1+ (1,0) [0|65535] "mv"  PC
 SG_ M2P_BMS_Status_B4 : 32|3@1+ (1,0) [0|7] ""  PC
 SG_ M2P_SOC_B4 : 35|10@1+ (0.1,0) [0|102.3] "%"  PC
 SG_ M2P_SOH_B4 : 45|8@1+ (1,0) [0|255] "%"  PC
 SG_ Reserved_20 : 53|11@1+ (1,0) [0|2047] ""  PC

CM_ SG_ 2334191249 M2P_Measure_Vol_B3_01 "汇流排3所有高压在线电柜外侧电压平均值    ";
CM_ SG_ 2334191249 M2P_Current_B3_01 "汇流排3所有电柜电流累加和";
CM_ SG_ 2334191249 M2P_PermitMaxCharge_I_B3_01 "汇流排3最大允许充电电流";
CM_ SG_ 2334191249 M2P_PermitMaxDisCharge_I_B3_01 "汇流排3最大允许放电电流";
CM_ SG_ 2334191250 M2P_Measure_Vol_B3_02 "汇流排3所有高压在线电柜外侧电压平均值    ";
CM_ SG_ 2334191250 M2P_Current_B3_02 "汇流排3所有电柜电流累加和";
CM_ SG_ 2334191250 M2P_PermitMaxCharge_I_B3_02 "汇流排3最大允许充电电流";
CM_ SG_ 2334191250 M2P_PermitMaxDisCharge_I_B3_02 "汇流排3最大允许放电电流";
CM_ SG_ 2334191251 M2P_Measure_Vol_B3_03 "汇流排3所有高压在线电柜外侧电压平均值    ";
CM_ SG_ 2334191251 M2P_Current_B3_03 "汇流排3所有电柜电流累加和";
CM_ SG_ 2334191251 M2P_PermitMaxCharge_I_B3_03 "汇流排3最大允许充电电流";
CM_ SG_ 2334191251 M2P_PermitMaxDisCharge_I_B3_03 "汇流排3最大允许放电电流";
CM_ SG_ 2334191252 M2P_Measure_Vol_B3_04 "汇流排3所有高压在线电柜外侧电压平均值    ";
CM_ SG_ 2334191252 M2P_Current_B3_04 "汇流排3所有电柜电流累加和";
CM_ SG_ 2334191252 M2P_PermitMaxCharge_I_B3_04 "汇流排3最大允许充电电流";
CM_ SG_ 2334191252 M2P_PermitMaxDisCharge_I_B3_04 "汇流排3最大允许放电电流";
CM_ SG_ 2334191253 M2P_Measure_Vol_B3_05 "汇流排3所有高压在线电柜外侧电压平均值    ";
CM_ SG_ 2334191253 M2P_Current_B3_05 "汇流排3所有电柜电流累加和";
CM_ SG_ 2334191253 M2P_PermitMaxCharge_I_B3_05 "汇流排3最大允许充电电流";
CM_ SG_ 2334191253 M2P_PermitMaxDisCharge_I_B3_05 "汇流排3最大允许放电电流";
CM_ SG_ 2334191254 M2P_Measure_Vol_B3_06 "汇流排3所有高压在线电柜外侧电压平均值    ";
CM_ SG_ 2334191254 M2P_Current_B3_06 "汇流排3所有电柜电流累加和";
CM_ SG_ 2334191254 M2P_PermitMaxCharge_I_B3_06 "汇流排3最大允许充电电流";
CM_ SG_ 2334191254 M2P_PermitMaxDisCharge_I_B3_06 "汇流排3最大允许放电电流";
CM_ SG_ 2334191255 M2P_Measure_Vol_B3_07 "汇流排3所有高压在线电柜外侧电压平均值    ";
CM_ SG_ 2334191255 M2P_Current_B3_07 "汇流排3所有电柜电流累加和";
CM_ SG_ 2334191255 M2P_PermitMaxCharge_I_B3_07 "汇流排3最大允许充电电流";
CM_ SG_ 2334191255 M2P_PermitMaxDisCharge_I_B3_07 "汇流排3最大允许放电电流";
CM_ SG_ 2334191256 M2P_Measure_Vol_B3_08 "汇流排3所有高压在线电柜外侧电压平均值    ";
CM_ SG_ 2334191256 M2P_Current_B3_08 "汇流排3所有电柜电流累加和";
CM_ SG_ 2334191256 M2P_PermitMaxCharge_I_B3_08 "汇流排3最大允许充电电流";
CM_ SG_ 2334191256 M2P_PermitMaxDisCharge_I_B3_08 "汇流排3最大允许放电电流";
CM_ SG_ 2334191257 M2P_Measure_Vol_B3_09 "汇流排3所有高压在线电柜外侧电压平均值    ";
CM_ SG_ 2334191257 M2P_Current_B3_09 "汇流排3所有电柜电流累加和";
CM_ SG_ 2334191257 M2P_PermitMaxCharge_I_B3_09 "汇流排3最大允许充电电流";
CM_ SG_ 2334191257 M2P_PermitMaxDisCharge_I_B3_09 "汇流排3最大允许放电电流";
CM_ SG_ 2334191258 M2P_Measure_Vol_B3_10 "汇流排3所有高压在线电柜外侧电压平均值    ";
CM_ SG_ 2334191258 M2P_Current_B3_10 "汇流排3所有电柜电流累加和";
CM_ SG_ 2334191258 M2P_PermitMaxCharge_I_B3_10 "汇流排3最大允许充电电流";
CM_ SG_ 2334191258 M2P_PermitMaxDisCharge_I_B3_10 "汇流排3最大允许放电电流";
CM_ SG_ 2334191259 M2P_Measure_Vol_B3_11 "汇流排3所有高压在线电柜外侧电压平均值    ";
CM_ SG_ 2334191259 M2P_Current_B3_11 "汇流排3所有电柜电流累加和";
CM_ SG_ 2334191259 M2P_PermitMaxCharge_I_B3_11 "汇流排3最大允许充电电流";
CM_ SG_ 2334191259 M2P_PermitMaxDisCharge_I_B3_11 "汇流排3最大允许放电电流";
CM_ SG_ 2334191260 M2P_Measure_Vol_B3_12 "汇流排3所有高压在线电柜外侧电压平均值    ";
CM_ SG_ 2334191260 M2P_Current_B3_12 "汇流排3所有电柜电流累加和";
CM_ SG_ 2334191260 M2P_PermitMaxCharge_I_B3_12 "汇流排3最大允许充电电流";
CM_ SG_ 2334191260 M2P_PermitMaxDisCharge_I_B3_12 "汇流排3最大允许放电电流";
CM_ SG_ 2334191261 M2P_Measure_Vol_B3_13 "汇流排3所有高压在线电柜外侧电压平均值    ";
CM_ SG_ 2334191261 M2P_Current_B3_13 "汇流排3所有电柜电流累加和";
CM_ SG_ 2334191261 M2P_PermitMaxCharge_I_B3_13 "汇流排3最大允许充电电流";
CM_ SG_ 2334191261 M2P_PermitMaxDisCharge_I_B3_13 "汇流排3最大允许放电电流";
CM_ SG_ 2334191262 M2P_Measure_Vol_B3_14 "汇流排3所有高压在线电柜外侧电压平均值    ";
CM_ SG_ 2334191262 M2P_Current_B3_14 "汇流排3所有电柜电流累加和";
CM_ SG_ 2334191262 M2P_PermitMaxCharge_I_B3_14 "汇流排3最大允许充电电流";
CM_ SG_ 2334191262 M2P_PermitMaxDisCharge_I_B3_14 "汇流排3最大允许放电电流";
CM_ SG_ 2334191263 M2P_Measure_Vol_B3_15 "汇流排3所有高压在线电柜外侧电压平均值    ";
CM_ SG_ 2334191263 M2P_Current_B3_15 "汇流排3所有电柜电流累加和";
CM_ SG_ 2334191263 M2P_PermitMaxCharge_I_B3_15 "汇流排3最大允许充电电流";
CM_ SG_ 2334191263 M2P_PermitMaxDisCharge_I_B3_15 "汇流排3最大允许放电电流";
CM_ SG_ 2334191264 M2P_Measure_Vol_B3_16 "汇流排3所有高压在线电柜外侧电压平均值    ";
CM_ SG_ 2334191264 M2P_Current_B3_16 "汇流排3所有电柜电流累加和";
CM_ SG_ 2334191264 M2P_PermitMaxCharge_I_B3_16 "汇流排3最大允许充电电流";
CM_ SG_ 2334191264 M2P_PermitMaxDisCharge_I_B3_16 "汇流排3最大允许放电电流";
CM_ SG_ 2334191265 M2P_Measure_Vol_B3_17 "汇流排3所有高压在线电柜外侧电压平均值    ";
CM_ SG_ 2334191265 M2P_Current_B3_17 "汇流排3所有电柜电流累加和";
CM_ SG_ 2334191265 M2P_PermitMaxCharge_I_B3_17 "汇流排3最大允许充电电流";
CM_ SG_ 2334191265 M2P_PermitMaxDisCharge_I_B3_17 "汇流排3最大允许放电电流";
CM_ SG_ 2334191266 M2P_Measure_Vol_B3_18 "汇流排3所有高压在线电柜外侧电压平均值    ";
CM_ SG_ 2334191266 M2P_Current_B3_18 "汇流排3所有电柜电流累加和";
CM_ SG_ 2334191266 M2P_PermitMaxCharge_I_B3_18 "汇流排3最大允许充电电流";
CM_ SG_ 2334191266 M2P_PermitMaxDisCharge_I_B3_18 "汇流排3最大允许放电电流";
CM_ SG_ 2334191267 M2P_Measure_Vol_B3_19 "汇流排3所有高压在线电柜外侧电压平均值    ";
CM_ SG_ 2334191267 M2P_Current_B3_19 "汇流排3所有电柜电流累加和";
CM_ SG_ 2334191267 M2P_PermitMaxCharge_I_B3_19 "汇流排3最大允许充电电流";
CM_ SG_ 2334191267 M2P_PermitMaxDisCharge_I_B3_19 "汇流排3最大允许放电电流";
CM_ SG_ 2334191268 M2P_Measure_Vol_B3_20 "汇流排3所有高压在线电柜外侧电压平均值    ";
CM_ SG_ 2334191268 M2P_Current_B3_20 "汇流排3所有电柜电流累加和";
CM_ SG_ 2334191268 M2P_PermitMaxCharge_I_B3_20 "汇流排3最大允许充电电流";
CM_ SG_ 2334191268 M2P_PermitMaxDisCharge_I_B3_20 "汇流排3最大允许放电电流";
CM_ SG_ 2334191269 M2P_Measure_Vol_B3_21 "汇流排3所有高压在线电柜外侧电压平均值    ";
CM_ SG_ 2334191269 M2P_Current_B3_21 "汇流排3所有电柜电流累加和";
CM_ SG_ 2334191269 M2P_PermitMaxCharge_I_B3_21 "汇流排3最大允许充电电流";
CM_ SG_ 2334191269 M2P_PermitMaxDisCharge_I_B3_21 "汇流排3最大允许放电电流";
CM_ SG_ 2334191270 M2P_Measure_Vol_B3_22 "汇流排3所有高压在线电柜外侧电压平均值    ";
CM_ SG_ 2334191270 M2P_Current_B3_22 "汇流排3所有电柜电流累加和";
CM_ SG_ 2334191270 M2P_PermitMaxCharge_I_B3_22 "汇流排3最大允许充电电流";
CM_ SG_ 2334191270 M2P_PermitMaxDisCharge_I_B3_22 "汇流排3最大允许放电电流";
CM_ SG_ 2334191271 M2P_Measure_Vol_B3_23 "汇流排3所有高压在线电柜外侧电压平均值    ";
CM_ SG_ 2334191271 M2P_Current_B3_23 "汇流排3所有电柜电流累加和";
CM_ SG_ 2334191271 M2P_PermitMaxCharge_I_B3_23 "汇流排3最大允许充电电流";
CM_ SG_ 2334191271 M2P_PermitMaxDisCharge_I_B3_23 "汇流排3最大允许放电电流";
CM_ SG_ 2334191272 M2P_Measure_Vol_B3_24 "汇流排3所有高压在线电柜外侧电压平均值    ";
CM_ SG_ 2334191272 M2P_Current_B3_24 "汇流排3所有电柜电流累加和";
CM_ SG_ 2334191272 M2P_PermitMaxCharge_I_B3_24 "汇流排3最大允许充电电流";
CM_ SG_ 2334191272 M2P_PermitMaxDisCharge_I_B3_24 "汇流排3最大允许放电电流";
CM_ SG_ 2334191273 M2P_Measure_Vol_B3_25 "汇流排3所有高压在线电柜外侧电压平均值    ";
CM_ SG_ 2334191273 M2P_Current_B3_25 "汇流排3所有电柜电流累加和";
CM_ SG_ 2334191273 M2P_PermitMaxCharge_I_B3_25 "汇流排3最大允许充电电流";
CM_ SG_ 2334191273 M2P_PermitMaxDisCharge_I_B3_25 "汇流排3最大允许放电电流";
CM_ SG_ 2334191274 M2P_Measure_Vol_B3_26 "汇流排3所有高压在线电柜外侧电压平均值    ";
CM_ SG_ 2334191274 M2P_Current_B3_26 "汇流排3所有电柜电流累加和";
CM_ SG_ 2334191274 M2P_PermitMaxCharge_I_B3_26 "汇流排3最大允许充电电流";
CM_ SG_ 2334191274 M2P_PermitMaxDisCharge_I_B3_26 "汇流排3最大允许放电电流";
CM_ SG_ 2334191275 M2P_Measure_Vol_B3_27 "汇流排3所有高压在线电柜外侧电压平均值    ";
CM_ SG_ 2334191275 M2P_Current_B3_27 "汇流排3所有电柜电流累加和";
CM_ SG_ 2334191275 M2P_PermitMaxCharge_I_B3_27 "汇流排3最大允许充电电流";
CM_ SG_ 2334191275 M2P_PermitMaxDisCharge_I_B3_27 "汇流排3最大允许放电电流";
CM_ SG_ 2334191276 M2P_Measure_Vol_B3_28 "汇流排3所有高压在线电柜外侧电压平均值    ";
CM_ SG_ 2334191276 M2P_Current_B3_28 "汇流排3所有电柜电流累加和";
CM_ SG_ 2334191276 M2P_PermitMaxCharge_I_B3_28 "汇流排3最大允许充电电流";
CM_ SG_ 2334191276 M2P_PermitMaxDisCharge_I_B3_28 "汇流排3最大允许放电电流";
CM_ SG_ 2334191277 M2P_Measure_Vol_B3_29 "汇流排3所有高压在线电柜外侧电压平均值    ";
CM_ SG_ 2334191277 M2P_Current_B3_29 "汇流排3所有电柜电流累加和";
CM_ SG_ 2334191277 M2P_PermitMaxCharge_I_B3_29 "汇流排3最大允许充电电流";
CM_ SG_ 2334191277 M2P_PermitMaxDisCharge_I_B3_29 "汇流排3最大允许放电电流";
CM_ SG_ 2334191278 M2P_Measure_Vol_B3_30 "汇流排3所有高压在线电柜外侧电压平均值    ";
CM_ SG_ 2334191278 M2P_Current_B3_30 "汇流排3所有电柜电流累加和";
CM_ SG_ 2334191278 M2P_PermitMaxCharge_I_B3_30 "汇流排3最大允许充电电流";
CM_ SG_ 2334191278 M2P_PermitMaxDisCharge_I_B3_30 "汇流排3最大允许放电电流";
CM_ SG_ 2334191279 M2P_Measure_Vol_B3_31 "汇流排3所有高压在线电柜外侧电压平均值    ";
CM_ SG_ 2334191279 M2P_Current_B3_31 "汇流排3所有电柜电流累加和";
CM_ SG_ 2334191279 M2P_PermitMaxCharge_I_B3_31 "汇流排3最大允许充电电流";
CM_ SG_ 2334191279 M2P_PermitMaxDisCharge_I_B3_31 "汇流排3最大允许放电电流";
CM_ SG_ 2334256785 M2P_PermitMaxVolt_B3_01 "汇流排3最高允许充电电压 （配置量）";
CM_ SG_ 2334256785 M2P_PermitMinVolt_B3_01 "汇流排3最低允许放电电压 （配置量）";
CM_ SG_ 2334256785 M2P_PermitMaxPow_Chg_B3_01 "汇流排3最大允许充电功率";
CM_ SG_ 2334256785 M2P_PermitMaxPow_DisChg_B3_01 "汇流排3最大允许放电功率";
CM_ SG_ 2334256786 M2P_PermitMaxVolt_B3_02 "汇流排3最高允许充电电压 （配置量）";
CM_ SG_ 2334256786 M2P_PermitMinVolt_B3_02 "汇流排3最低允许放电电压 （配置量）";
CM_ SG_ 2334256786 M2P_PermitMaxPow_Chg_B3_02 "汇流排3最大允许充电功率";
CM_ SG_ 2334256786 M2P_PermitMaxPow_DisChg_B3_02 "汇流排3最大允许放电功率";
CM_ SG_ 2334256787 M2P_PermitMaxVolt_B3_03 "汇流排3最高允许充电电压 （配置量）";
CM_ SG_ 2334256787 M2P_PermitMinVolt_B3_03 "汇流排3最低允许放电电压 （配置量）";
CM_ SG_ 2334256787 M2P_PermitMaxPow_Chg_B3_03 "汇流排3最大允许充电功率";
CM_ SG_ 2334256787 M2P_PermitMaxPow_DisChg_B3_03 "汇流排3最大允许放电功率";
CM_ SG_ 2334256788 M2P_PermitMaxVolt_B3_04 "汇流排3最高允许充电电压 （配置量）";
CM_ SG_ 2334256788 M2P_PermitMinVolt_B3_04 "汇流排3最低允许放电电压 （配置量）";
CM_ SG_ 2334256788 M2P_PermitMaxPow_Chg_B3_04 "汇流排3最大允许充电功率";
CM_ SG_ 2334256788 M2P_PermitMaxPow_DisChg_B3_04 "汇流排3最大允许放电功率";
CM_ SG_ 2334256789 M2P_PermitMaxVolt_B3_05 "汇流排3最高允许充电电压 （配置量）";
CM_ SG_ 2334256789 M2P_PermitMinVolt_B3_05 "汇流排3最低允许放电电压 （配置量）";
CM_ SG_ 2334256789 M2P_PermitMaxPow_Chg_B3_05 "汇流排3最大允许充电功率";
CM_ SG_ 2334256789 M2P_PermitMaxPow_DisChg_B3_05 "汇流排3最大允许放电功率";
CM_ SG_ 2334256790 M2P_PermitMaxVolt_B3_06 "汇流排3最高允许充电电压 （配置量）";
CM_ SG_ 2334256790 M2P_PermitMinVolt_B3_06 "汇流排3最低允许放电电压 （配置量）";
CM_ SG_ 2334256790 M2P_PermitMaxPow_Chg_B3_06 "汇流排3最大允许充电功率";
CM_ SG_ 2334256790 M2P_PermitMaxPow_DisChg_B3_06 "汇流排3最大允许放电功率";
CM_ SG_ 2334256791 M2P_PermitMaxVolt_B3_07 "汇流排3最高允许充电电压 （配置量）";
CM_ SG_ 2334256791 M2P_PermitMinVolt_B3_07 "汇流排3最低允许放电电压 （配置量）";
CM_ SG_ 2334256791 M2P_PermitMaxPow_Chg_B3_07 "汇流排3最大允许充电功率";
CM_ SG_ 2334256791 M2P_PermitMaxPow_DisChg_B3_07 "汇流排3最大允许放电功率";
CM_ SG_ 2334256792 M2P_PermitMaxVolt_B3_08 "汇流排3最高允许充电电压 （配置量）";
CM_ SG_ 2334256792 M2P_PermitMinVolt_B3_08 "汇流排3最低允许放电电压 （配置量）";
CM_ SG_ 2334256792 M2P_PermitMaxPow_Chg_B3_08 "汇流排3最大允许充电功率";
CM_ SG_ 2334256792 M2P_PermitMaxPow_DisChg_B3_08 "汇流排3最大允许放电功率";
CM_ SG_ 2334256793 M2P_PermitMaxVolt_B3_09 "汇流排3最高允许充电电压 （配置量）";
CM_ SG_ 2334256793 M2P_PermitMinVolt_B3_09 "汇流排3最低允许放电电压 （配置量）";
CM_ SG_ 2334256793 M2P_PermitMaxPow_Chg_B3_09 "汇流排3最大允许充电功率";
CM_ SG_ 2334256793 M2P_PermitMaxPow_DisChg_B3_09 "汇流排3最大允许放电功率";
CM_ SG_ 2334256794 M2P_PermitMaxVolt_B3_10 "汇流排3最高允许充电电压 （配置量）";
CM_ SG_ 2334256794 M2P_PermitMinVolt_B3_10 "汇流排3最低允许放电电压 （配置量）";
CM_ SG_ 2334256794 M2P_PermitMaxPow_Chg_B3_10 "汇流排3最大允许充电功率";
CM_ SG_ 2334256794 M2P_PermitMaxPow_DisChg_B3_10 "汇流排3最大允许放电功率";
CM_ SG_ 2334256795 M2P_PermitMaxVolt_B3_11 "汇流排3最高允许充电电压 （配置量）";
CM_ SG_ 2334256795 M2P_PermitMinVolt_B3_11 "汇流排3最低允许放电电压 （配置量）";
CM_ SG_ 2334256795 M2P_PermitMaxPow_Chg_B3_11 "汇流排3最大允许充电功率";
CM_ SG_ 2334256795 M2P_PermitMaxPow_DisChg_B3_11 "汇流排3最大允许放电功率";
CM_ SG_ 2334256796 M2P_PermitMaxVolt_B3_12 "汇流排3最高允许充电电压 （配置量）";
CM_ SG_ 2334256796 M2P_PermitMinVolt_B3_12 "汇流排3最低允许放电电压 （配置量）";
CM_ SG_ 2334256796 M2P_PermitMaxPow_Chg_B3_12 "汇流排3最大允许充电功率";
CM_ SG_ 2334256796 M2P_PermitMaxPow_DisChg_B3_12 "汇流排3最大允许放电功率";
CM_ SG_ 2334256797 M2P_PermitMaxVolt_B3_13 "汇流排3最高允许充电电压 （配置量）";
CM_ SG_ 2334256797 M2P_PermitMinVolt_B3_13 "汇流排3最低允许放电电压 （配置量）";
CM_ SG_ 2334256797 M2P_PermitMaxPow_Chg_B3_13 "汇流排3最大允许充电功率";
CM_ SG_ 2334256797 M2P_PermitMaxPow_DisChg_B3_13 "汇流排3最大允许放电功率";
CM_ SG_ 2334256798 M2P_PermitMaxVolt_B3_14 "汇流排3最高允许充电电压 （配置量）";
CM_ SG_ 2334256798 M2P_PermitMinVolt_B3_14 "汇流排3最低允许放电电压 （配置量）";
CM_ SG_ 2334256798 M2P_PermitMaxPow_Chg_B3_14 "汇流排3最大允许充电功率";
CM_ SG_ 2334256798 M2P_PermitMaxPow_DisChg_B3_14 "汇流排3最大允许放电功率";
CM_ SG_ 2334256799 M2P_PermitMaxVolt_B3_15 "汇流排3最高允许充电电压 （配置量）";
CM_ SG_ 2334256799 M2P_PermitMinVolt_B3_15 "汇流排3最低允许放电电压 （配置量）";
CM_ SG_ 2334256799 M2P_PermitMaxPow_Chg_B3_15 "汇流排3最大允许充电功率";
CM_ SG_ 2334256799 M2P_PermitMaxPow_DisChg_B3_15 "汇流排3最大允许放电功率";
CM_ SG_ 2334256800 M2P_PermitMaxVolt_B3_16 "汇流排3最高允许充电电压 （配置量）";
CM_ SG_ 2334256800 M2P_PermitMinVolt_B3_16 "汇流排3最低允许放电电压 （配置量）";
CM_ SG_ 2334256800 M2P_PermitMaxPow_Chg_B3_16 "汇流排3最大允许充电功率";
CM_ SG_ 2334256800 M2P_PermitMaxPow_DisChg_B3_16 "汇流排3最大允许放电功率";
CM_ SG_ 2334256801 M2P_PermitMaxVolt_B3_17 "汇流排3最高允许充电电压 （配置量）";
CM_ SG_ 2334256801 M2P_PermitMinVolt_B3_17 "汇流排3最低允许放电电压 （配置量）";
CM_ SG_ 2334256801 M2P_PermitMaxPow_Chg_B3_17 "汇流排3最大允许充电功率";
CM_ SG_ 2334256801 M2P_PermitMaxPow_DisChg_B3_17 "汇流排3最大允许放电功率";
CM_ SG_ 2334256802 M2P_PermitMaxVolt_B3_18 "汇流排3最高允许充电电压 （配置量）";
CM_ SG_ 2334256802 M2P_PermitMinVolt_B3_18 "汇流排3最低允许放电电压 （配置量）";
CM_ SG_ 2334256802 M2P_PermitMaxPow_Chg_B3_18 "汇流排3最大允许充电功率";
CM_ SG_ 2334256802 M2P_PermitMaxPow_DisChg_B3_18 "汇流排3最大允许放电功率";
CM_ SG_ 2334256803 M2P_PermitMaxVolt_B3_19 "汇流排3最高允许充电电压 （配置量）";
CM_ SG_ 2334256803 M2P_PermitMinVolt_B3_19 "汇流排3最低允许放电电压 （配置量）";
CM_ SG_ 2334256803 M2P_PermitMaxPow_Chg_B3_19 "汇流排3最大允许充电功率";
CM_ SG_ 2334256803 M2P_PermitMaxPow_DisChg_B3_19 "汇流排3最大允许放电功率";
CM_ SG_ 2334256804 M2P_PermitMaxVolt_B3_20 "汇流排3最高允许充电电压 （配置量）";
CM_ SG_ 2334256804 M2P_PermitMinVolt_B3_20 "汇流排3最低允许放电电压 （配置量）";
CM_ SG_ 2334256804 M2P_PermitMaxPow_Chg_B3_20 "汇流排3最大允许充电功率";
CM_ SG_ 2334256804 M2P_PermitMaxPow_DisChg_B3_20 "汇流排3最大允许放电功率";
CM_ SG_ 2334256805 M2P_PermitMaxVolt_B3_21 "汇流排3最高允许充电电压 （配置量）";
CM_ SG_ 2334256805 M2P_PermitMinVolt_B3_21 "汇流排3最低允许放电电压 （配置量）";
CM_ SG_ 2334256805 M2P_PermitMaxPow_Chg_B3_21 "汇流排3最大允许充电功率";
CM_ SG_ 2334256805 M2P_PermitMaxPow_DisChg_B3_21 "汇流排3最大允许放电功率";
CM_ SG_ 2334256806 M2P_PermitMaxVolt_B3_22 "汇流排3最高允许充电电压 （配置量）";
CM_ SG_ 2334256806 M2P_PermitMinVolt_B3_22 "汇流排3最低允许放电电压 （配置量）";
CM_ SG_ 2334256806 M2P_PermitMaxPow_Chg_B3_22 "汇流排3最大允许充电功率";
CM_ SG_ 2334256806 M2P_PermitMaxPow_DisChg_B3_22 "汇流排3最大允许放电功率";
CM_ SG_ 2334256807 M2P_PermitMaxVolt_B3_23 "汇流排3最高允许充电电压 （配置量）";
CM_ SG_ 2334256807 M2P_PermitMinVolt_B3_23 "汇流排3最低允许放电电压 （配置量）";
CM_ SG_ 2334256807 M2P_PermitMaxPow_Chg_B3_23 "汇流排3最大允许充电功率";
CM_ SG_ 2334256807 M2P_PermitMaxPow_DisChg_B3_23 "汇流排3最大允许放电功率";
CM_ SG_ 2334256808 M2P_PermitMaxVolt_B3_24 "汇流排3最高允许充电电压 （配置量）";
CM_ SG_ 2334256808 M2P_PermitMinVolt_B3_24 "汇流排3最低允许放电电压 （配置量）";
CM_ SG_ 2334256808 M2P_PermitMaxPow_Chg_B3_24 "汇流排3最大允许充电功率";
CM_ SG_ 2334256808 M2P_PermitMaxPow_DisChg_B3_24 "汇流排3最大允许放电功率";
CM_ SG_ 2334256809 M2P_PermitMaxVolt_B3_25 "汇流排3最高允许充电电压 （配置量）";
CM_ SG_ 2334256809 M2P_PermitMinVolt_B3_25 "汇流排3最低允许放电电压 （配置量）";
CM_ SG_ 2334256809 M2P_PermitMaxPow_Chg_B3_25 "汇流排3最大允许充电功率";
CM_ SG_ 2334256809 M2P_PermitMaxPow_DisChg_B3_25 "汇流排3最大允许放电功率";
CM_ SG_ 2334256810 M2P_PermitMaxVolt_B3_26 "汇流排3最高允许充电电压 （配置量）";
CM_ SG_ 2334256810 M2P_PermitMinVolt_B3_26 "汇流排3最低允许放电电压 （配置量）";
CM_ SG_ 2334256810 M2P_PermitMaxPow_Chg_B3_26 "汇流排3最大允许充电功率";
CM_ SG_ 2334256810 M2P_PermitMaxPow_DisChg_B3_26 "汇流排3最大允许放电功率";
CM_ SG_ 2334256811 M2P_PermitMaxVolt_B3_27 "汇流排3最高允许充电电压 （配置量）";
CM_ SG_ 2334256811 M2P_PermitMinVolt_B3_27 "汇流排3最低允许放电电压 （配置量）";
CM_ SG_ 2334256811 M2P_PermitMaxPow_Chg_B3_27 "汇流排3最大允许充电功率";
CM_ SG_ 2334256811 M2P_PermitMaxPow_DisChg_B3_27 "汇流排3最大允许放电功率";
CM_ SG_ 2334256812 M2P_PermitMaxVolt_B3_28 "汇流排3最高允许充电电压 （配置量）";
CM_ SG_ 2334256812 M2P_PermitMinVolt_B3_28 "汇流排3最低允许放电电压 （配置量）";
CM_ SG_ 2334256812 M2P_PermitMaxPow_Chg_B3_28 "汇流排3最大允许充电功率";
CM_ SG_ 2334256812 M2P_PermitMaxPow_DisChg_B3_28 "汇流排3最大允许放电功率";
CM_ SG_ 2334256813 M2P_PermitMaxVolt_B3_29 "汇流排3最高允许充电电压 （配置量）";
CM_ SG_ 2334256813 M2P_PermitMinVolt_B3_29 "汇流排3最低允许放电电压 （配置量）";
CM_ SG_ 2334256813 M2P_PermitMaxPow_Chg_B3_29 "汇流排3最大允许充电功率";
CM_ SG_ 2334256813 M2P_PermitMaxPow_DisChg_B3_29 "汇流排3最大允许放电功率";
CM_ SG_ 2334256814 M2P_PermitMaxVolt_B3_30 "汇流排3最高允许充电电压 （配置量）";
CM_ SG_ 2334256814 M2P_PermitMinVolt_B3_30 "汇流排3最低允许放电电压 （配置量）";
CM_ SG_ 2334256814 M2P_PermitMaxPow_Chg_B3_30 "汇流排3最大允许充电功率";
CM_ SG_ 2334256814 M2P_PermitMaxPow_DisChg_B3_30 "汇流排3最大允许放电功率";
CM_ SG_ 2334256815 M2P_PermitMaxVolt_B3_31 "汇流排3最高允许充电电压 （配置量）";
CM_ SG_ 2334256815 M2P_PermitMinVolt_B3_31 "汇流排3最低允许放电电压 （配置量）";
CM_ SG_ 2334256815 M2P_PermitMaxPow_Chg_B3_31 "汇流排3最大允许充电功率";
CM_ SG_ 2334256815 M2P_PermitMaxPow_DisChg_B3_31 "汇流排3最大允许放电功率";
CM_ SG_ 2334322321 M2P_Power_B3_01 "汇流排3实时功率";
CM_ SG_ 2334322321 M2P_SysremEngy_Chg_B3_01 "汇流排3充电剩余能量";
CM_ SG_ 2334322321 M2P_SysremEngy_DisChg_B3_01 "汇流排3放电剩余能量";
CM_ SG_ 2334322321 M2P_SysMaxVolt_B3_01 "汇流排3单体最大电压  ";
CM_ SG_ 2334322322 M2P_Power_B3_02 "汇流排3实时功率";
CM_ SG_ 2334322322 M2P_SysremEngy_Chg_B3_02 "汇流排3充电剩余能量";
CM_ SG_ 2334322322 M2P_SysremEngy_DisChg_B3_02 "汇流排3放电剩余能量";
CM_ SG_ 2334322322 M2P_SysMaxVolt_B3_02 "汇流排3单体最大电压  ";
CM_ SG_ 2334322323 M2P_Power_B3_03 "汇流排3实时功率";
CM_ SG_ 2334322323 M2P_SysremEngy_Chg_B3_03 "汇流排3充电剩余能量";
CM_ SG_ 2334322323 M2P_SysremEngy_DisChg_B3_03 "汇流排3放电剩余能量";
CM_ SG_ 2334322323 M2P_SysMaxVolt_B3_03 "汇流排3单体最大电压  ";
CM_ SG_ 2334322324 M2P_Power_B3_04 "汇流排3实时功率";
CM_ SG_ 2334322324 M2P_SysremEngy_Chg_B3_04 "汇流排3充电剩余能量";
CM_ SG_ 2334322324 M2P_SysremEngy_DisChg_B3_04 "汇流排3放电剩余能量";
CM_ SG_ 2334322324 M2P_SysMaxVolt_B3_04 "汇流排3单体最大电压  ";
CM_ SG_ 2334322325 M2P_Power_B3_05 "汇流排3实时功率";
CM_ SG_ 2334322325 M2P_SysremEngy_Chg_B3_05 "汇流排3充电剩余能量";
CM_ SG_ 2334322325 M2P_SysremEngy_DisChg_B3_05 "汇流排3放电剩余能量";
CM_ SG_ 2334322325 M2P_SysMaxVolt_B3_05 "汇流排3单体最大电压  ";
CM_ SG_ 2334322326 M2P_Power_B3_06 "汇流排3实时功率";
CM_ SG_ 2334322326 M2P_SysremEngy_Chg_B3_06 "汇流排3充电剩余能量";
CM_ SG_ 2334322326 M2P_SysremEngy_DisChg_B3_06 "汇流排3放电剩余能量";
CM_ SG_ 2334322326 M2P_SysMaxVolt_B3_06 "汇流排3单体最大电压  ";
CM_ SG_ 2334322327 M2P_Power_B3_07 "汇流排3实时功率";
CM_ SG_ 2334322327 M2P_SysremEngy_Chg_B3_07 "汇流排3充电剩余能量";
CM_ SG_ 2334322327 M2P_SysremEngy_DisChg_B3_07 "汇流排3放电剩余能量";
CM_ SG_ 2334322327 M2P_SysMaxVolt_B3_07 "汇流排3单体最大电压  ";
CM_ SG_ 2334322328 M2P_Power_B3_08 "汇流排3实时功率";
CM_ SG_ 2334322328 M2P_SysremEngy_Chg_B3_08 "汇流排3充电剩余能量";
CM_ SG_ 2334322328 M2P_SysremEngy_DisChg_B3_08 "汇流排3放电剩余能量";
CM_ SG_ 2334322328 M2P_SysMaxVolt_B3_08 "汇流排3单体最大电压  ";
CM_ SG_ 2334322329 M2P_Power_B3_09 "汇流排3实时功率";
CM_ SG_ 2334322329 M2P_SysremEngy_Chg_B3_09 "汇流排3充电剩余能量";
CM_ SG_ 2334322329 M2P_SysremEngy_DisChg_B3_09 "汇流排3放电剩余能量";
CM_ SG_ 2334322329 M2P_SysMaxVolt_B3_09 "汇流排3单体最大电压  ";
CM_ SG_ 2334322330 M2P_Power_B3_10 "汇流排3实时功率";
CM_ SG_ 2334322330 M2P_SysremEngy_Chg_B3_10 "汇流排3充电剩余能量";
CM_ SG_ 2334322330 M2P_SysremEngy_DisChg_B3_10 "汇流排3放电剩余能量";
CM_ SG_ 2334322330 M2P_SysMaxVolt_B3_10 "汇流排3单体最大电压  ";
CM_ SG_ 2334322331 M2P_Power_B3_11 "汇流排3实时功率";
CM_ SG_ 2334322331 M2P_SysremEngy_Chg_B3_11 "汇流排3充电剩余能量";
CM_ SG_ 2334322331 M2P_SysremEngy_DisChg_B3_11 "汇流排3放电剩余能量";
CM_ SG_ 2334322331 M2P_SysMaxVolt_B3_11 "汇流排3单体最大电压  ";
CM_ SG_ 2334322332 M2P_Power_B3_12 "汇流排3实时功率";
CM_ SG_ 2334322332 M2P_SysremEngy_Chg_B3_12 "汇流排3充电剩余能量";
CM_ SG_ 2334322332 M2P_SysremEngy_DisChg_B3_12 "汇流排3放电剩余能量";
CM_ SG_ 2334322332 M2P_SysMaxVolt_B3_12 "汇流排3单体最大电压  ";
CM_ SG_ 2334322333 M2P_Power_B3_13 "汇流排3实时功率";
CM_ SG_ 2334322333 M2P_SysremEngy_Chg_B3_13 "汇流排3充电剩余能量";
CM_ SG_ 2334322333 M2P_SysremEngy_DisChg_B3_13 "汇流排3放电剩余能量";
CM_ SG_ 2334322333 M2P_SysMaxVolt_B3_13 "汇流排3单体最大电压  ";
CM_ SG_ 2334322334 M2P_Power_B3_14 "汇流排3实时功率";
CM_ SG_ 2334322334 M2P_SysremEngy_Chg_B3_14 "汇流排3充电剩余能量";
CM_ SG_ 2334322334 M2P_SysremEngy_DisChg_B3_14 "汇流排3放电剩余能量";
CM_ SG_ 2334322334 M2P_SysMaxVolt_B3_14 "汇流排3单体最大电压  ";
CM_ SG_ 2334322335 M2P_Power_B3_15 "汇流排3实时功率";
CM_ SG_ 2334322335 M2P_SysremEngy_Chg_B3_15 "汇流排3充电剩余能量";
CM_ SG_ 2334322335 M2P_SysremEngy_DisChg_B3_15 "汇流排3放电剩余能量";
CM_ SG_ 2334322335 M2P_SysMaxVolt_B3_15 "汇流排3单体最大电压  ";
CM_ SG_ 2334322336 M2P_Power_B3_16 "汇流排3实时功率";
CM_ SG_ 2334322336 M2P_SysremEngy_Chg_B3_16 "汇流排3充电剩余能量";
CM_ SG_ 2334322336 M2P_SysremEngy_DisChg_B3_16 "汇流排3放电剩余能量";
CM_ SG_ 2334322336 M2P_SysMaxVolt_B3_16 "汇流排3单体最大电压  ";
CM_ SG_ 2334322337 M2P_Power_B3_17 "汇流排3实时功率";
CM_ SG_ 2334322337 M2P_SysremEngy_Chg_B3_17 "汇流排3充电剩余能量";
CM_ SG_ 2334322337 M2P_SysremEngy_DisChg_B3_17 "汇流排3放电剩余能量";
CM_ SG_ 2334322337 M2P_SysMaxVolt_B3_17 "汇流排3单体最大电压  ";
CM_ SG_ 2334322338 M2P_Power_B3_18 "汇流排3实时功率";
CM_ SG_ 2334322338 M2P_SysremEngy_Chg_B3_18 "汇流排3充电剩余能量";
CM_ SG_ 2334322338 M2P_SysremEngy_DisChg_B3_18 "汇流排3放电剩余能量";
CM_ SG_ 2334322338 M2P_SysMaxVolt_B3_18 "汇流排3单体最大电压  ";
CM_ SG_ 2334322339 M2P_Power_B3_19 "汇流排3实时功率";
CM_ SG_ 2334322339 M2P_SysremEngy_Chg_B3_19 "汇流排3充电剩余能量";
CM_ SG_ 2334322339 M2P_SysremEngy_DisChg_B3_19 "汇流排3放电剩余能量";
CM_ SG_ 2334322339 M2P_SysMaxVolt_B3_19 "汇流排3单体最大电压  ";
CM_ SG_ 2334322340 M2P_Power_B3_20 "汇流排3实时功率";
CM_ SG_ 2334322340 M2P_SysremEngy_Chg_B3_20 "汇流排3充电剩余能量";
CM_ SG_ 2334322340 M2P_SysremEngy_DisChg_B3_20 "汇流排3放电剩余能量";
CM_ SG_ 2334322340 M2P_SysMaxVolt_B3_20 "汇流排3单体最大电压  ";
CM_ SG_ 2334322341 M2P_Power_B3_21 "汇流排3实时功率";
CM_ SG_ 2334322341 M2P_SysremEngy_Chg_B3_21 "汇流排3充电剩余能量";
CM_ SG_ 2334322341 M2P_SysremEngy_DisChg_B3_21 "汇流排3放电剩余能量";
CM_ SG_ 2334322341 M2P_SysMaxVolt_B3_21 "汇流排3单体最大电压  ";
CM_ SG_ 2334322342 M2P_Power_B3_22 "汇流排3实时功率";
CM_ SG_ 2334322342 M2P_SysremEngy_Chg_B3_22 "汇流排3充电剩余能量";
CM_ SG_ 2334322342 M2P_SysremEngy_DisChg_B3_22 "汇流排3放电剩余能量";
CM_ SG_ 2334322342 M2P_SysMaxVolt_B3_22 "汇流排3单体最大电压  ";
CM_ SG_ 2334322343 M2P_Power_B3_23 "汇流排3实时功率";
CM_ SG_ 2334322343 M2P_SysremEngy_Chg_B3_23 "汇流排3充电剩余能量";
CM_ SG_ 2334322343 M2P_SysremEngy_DisChg_B3_23 "汇流排3放电剩余能量";
CM_ SG_ 2334322343 M2P_SysMaxVolt_B3_23 "汇流排3单体最大电压  ";
CM_ SG_ 2334322344 M2P_Power_B3_24 "汇流排3实时功率";
CM_ SG_ 2334322344 M2P_SysremEngy_Chg_B3_24 "汇流排3充电剩余能量";
CM_ SG_ 2334322344 M2P_SysremEngy_DisChg_B3_24 "汇流排3放电剩余能量";
CM_ SG_ 2334322344 M2P_SysMaxVolt_B3_24 "汇流排3单体最大电压  ";
CM_ SG_ 2334322345 M2P_Power_B3_25 "汇流排3实时功率";
CM_ SG_ 2334322345 M2P_SysremEngy_Chg_B3_25 "汇流排3充电剩余能量";
CM_ SG_ 2334322345 M2P_SysremEngy_DisChg_B3_25 "汇流排3放电剩余能量";
CM_ SG_ 2334322345 M2P_SysMaxVolt_B3_25 "汇流排3单体最大电压  ";
CM_ SG_ 2334322346 M2P_Power_B3_26 "汇流排3实时功率";
CM_ SG_ 2334322346 M2P_SysremEngy_Chg_B3_26 "汇流排3充电剩余能量";
CM_ SG_ 2334322346 M2P_SysremEngy_DisChg_B3_26 "汇流排3放电剩余能量";
CM_ SG_ 2334322346 M2P_SysMaxVolt_B3_26 "汇流排3单体最大电压  ";
CM_ SG_ 2334322347 M2P_Power_B3_27 "汇流排3实时功率";
CM_ SG_ 2334322347 M2P_SysremEngy_Chg_B3_27 "汇流排3充电剩余能量";
CM_ SG_ 2334322347 M2P_SysremEngy_DisChg_B3_27 "汇流排3放电剩余能量";
CM_ SG_ 2334322347 M2P_SysMaxVolt_B3_27 "汇流排3单体最大电压  ";
CM_ SG_ 2334322348 M2P_Power_B3_28 "汇流排3实时功率";
CM_ SG_ 2334322348 M2P_SysremEngy_Chg_B3_28 "汇流排3充电剩余能量";
CM_ SG_ 2334322348 M2P_SysremEngy_DisChg_B3_28 "汇流排3放电剩余能量";
CM_ SG_ 2334322348 M2P_SysMaxVolt_B3_28 "汇流排3单体最大电压  ";
CM_ SG_ 2334322349 M2P_Power_B3_29 "汇流排3实时功率";
CM_ SG_ 2334322349 M2P_SysremEngy_Chg_B3_29 "汇流排3充电剩余能量";
CM_ SG_ 2334322349 M2P_SysremEngy_DisChg_B3_29 "汇流排3放电剩余能量";
CM_ SG_ 2334322349 M2P_SysMaxVolt_B3_29 "汇流排3单体最大电压  ";
CM_ SG_ 2334322350 M2P_Power_B3_30 "汇流排3实时功率";
CM_ SG_ 2334322350 M2P_SysremEngy_Chg_B3_30 "汇流排3充电剩余能量";
CM_ SG_ 2334322350 M2P_SysremEngy_DisChg_B3_30 "汇流排3放电剩余能量";
CM_ SG_ 2334322350 M2P_SysMaxVolt_B3_30 "汇流排3单体最大电压  ";
CM_ SG_ 2334322351 M2P_Power_B3_31 "汇流排3实时功率";
CM_ SG_ 2334322351 M2P_SysremEngy_Chg_B3_31 "汇流排3充电剩余能量";
CM_ SG_ 2334322351 M2P_SysremEngy_DisChg_B3_31 "汇流排3放电剩余能量";
CM_ SG_ 2334322351 M2P_SysMaxVolt_B3_31 "汇流排3单体最大电压  ";
CM_ SG_ 2334387857 M2P_SysMinVolt_B3_01 "汇流排3单体最小电压";
CM_ SG_ 2334387857 M2P_SysAvgVolt_B3_01 "汇流排3单体平均电压";
CM_ SG_ 2334387857 M2P_BMS_Status_B3 "汇流排3能量状态";
CM_ SG_ 2334387857 M2P_SOC_B3 "汇流排3系统SOC";
CM_ SG_ 2334387857 M2P_SOH_B3 "汇流排3系统SOH";
CM_ SG_ 2334387857 Reserved_01 "预留";
CM_ SG_ 2334387858 M2P_SysMinVolt_B3_02 "汇流排3单体最小电压";
CM_ SG_ 2334387858 M2P_SysAvgVolt_B3_02 "汇流排3单体平均电压";
CM_ SG_ 2334387858 M2P_BMS_Status_B3 "汇流排3能量状态";
CM_ SG_ 2334387858 M2P_SOC_B3 "汇流排3系统SOC";
CM_ SG_ 2334387858 M2P_SOH_B3 "汇流排3系统SOH";
CM_ SG_ 2334387858 Reserved_02 "预留";
CM_ SG_ 2334387859 M2P_SysMinVolt_B3_03 "汇流排3单体最小电压";
CM_ SG_ 2334387859 M2P_SysAvgVolt_B3_03 "汇流排3单体平均电压";
CM_ SG_ 2334387859 M2P_BMS_Status_B3 "汇流排3能量状态";
CM_ SG_ 2334387859 M2P_SOC_B3 "汇流排3系统SOC";
CM_ SG_ 2334387859 M2P_SOH_B3 "汇流排3系统SOH";
CM_ SG_ 2334387859 Reserved_03 "预留";
CM_ SG_ 2334387860 M2P_SysMinVolt_B3_04 "汇流排3单体最小电压";
CM_ SG_ 2334387860 M2P_SysAvgVolt_B3_04 "汇流排3单体平均电压";
CM_ SG_ 2334387860 M2P_BMS_Status_B3 "汇流排3能量状态";
CM_ SG_ 2334387860 M2P_SOC_B3 "汇流排3系统SOC";
CM_ SG_ 2334387860 M2P_SOH_B3 "汇流排3系统SOH";
CM_ SG_ 2334387860 Reserved_04 "预留";
CM_ SG_ 2334387861 M2P_SysMinVolt_B3_05 "汇流排3单体最小电压";
CM_ SG_ 2334387861 M2P_SysAvgVolt_B3_05 "汇流排3单体平均电压";
CM_ SG_ 2334387861 M2P_BMS_Status_B3 "汇流排3能量状态";
CM_ SG_ 2334387861 M2P_SOC_B3 "汇流排3系统SOC";
CM_ SG_ 2334387861 M2P_SOH_B3 "汇流排3系统SOH";
CM_ SG_ 2334387861 Reserved_05 "预留";
CM_ SG_ 2334387862 M2P_SysMinVolt_B3_06 "汇流排3单体最小电压";
CM_ SG_ 2334387862 M2P_SysAvgVolt_B3_06 "汇流排3单体平均电压";
CM_ SG_ 2334387862 M2P_BMS_Status_B3 "汇流排3能量状态";
CM_ SG_ 2334387862 M2P_SOC_B3 "汇流排3系统SOC";
CM_ SG_ 2334387862 M2P_SOH_B3 "汇流排3系统SOH";
CM_ SG_ 2334387862 Reserved_06 "预留";
CM_ SG_ 2334387863 M2P_SysMinVolt_B3_07 "汇流排3单体最小电压";
CM_ SG_ 2334387863 M2P_SysAvgVolt_B3_07 "汇流排3单体平均电压";
CM_ SG_ 2334387863 M2P_BMS_Status_B3 "汇流排3能量状态";
CM_ SG_ 2334387863 M2P_SOC_B3 "汇流排3系统SOC";
CM_ SG_ 2334387863 M2P_SOH_B3 "汇流排3系统SOH";
CM_ SG_ 2334387863 Reserved_07 "预留";
CM_ SG_ 2334387864 M2P_SysMinVolt_B3_08 "汇流排3单体最小电压";
CM_ SG_ 2334387864 M2P_SysAvgVolt_B3_08 "汇流排3单体平均电压";
CM_ SG_ 2334387864 M2P_BMS_Status_B3 "汇流排3能量状态";
CM_ SG_ 2334387864 M2P_SOC_B3 "汇流排3系统SOC";
CM_ SG_ 2334387864 M2P_SOH_B3 "汇流排3系统SOH";
CM_ SG_ 2334387864 Reserved_08 "预留";
CM_ SG_ 2334387865 M2P_SysMinVolt_B3_09 "汇流排3单体最小电压";
CM_ SG_ 2334387865 M2P_SysAvgVolt_B3_09 "汇流排3单体平均电压";
CM_ SG_ 2334387865 M2P_BMS_Status_B3 "汇流排3能量状态";
CM_ SG_ 2334387865 M2P_SOC_B3 "汇流排3系统SOC";
CM_ SG_ 2334387865 M2P_SOH_B3 "汇流排3系统SOH";
CM_ SG_ 2334387865 Reserved_09 "预留";
CM_ SG_ 2334387866 M2P_SysMinVolt_B3_10 "汇流排3单体最小电压";
CM_ SG_ 2334387866 M2P_SysAvgVolt_B3_10 "汇流排3单体平均电压";
CM_ SG_ 2334387866 M2P_BMS_Status_B3 "汇流排3能量状态";
CM_ SG_ 2334387866 M2P_SOC_B3 "汇流排3系统SOC";
CM_ SG_ 2334387866 M2P_SOH_B3 "汇流排3系统SOH";
CM_ SG_ 2334387866 Reserved_10 "预留";
CM_ SG_ 2334387867 M2P_SysMinVolt_B3_11 "汇流排3单体最小电压";
CM_ SG_ 2334387867 M2P_SysAvgVolt_B3_11 "汇流排3单体平均电压";
CM_ SG_ 2334387867 M2P_BMS_Status_B3 "汇流排3能量状态";
CM_ SG_ 2334387867 M2P_SOC_B3 "汇流排3系统SOC";
CM_ SG_ 2334387867 M2P_SOH_B3 "汇流排3系统SOH";
CM_ SG_ 2334387867 Reserved_11 "预留";
CM_ SG_ 2334387868 M2P_SysMinVolt_B3_12 "汇流排3单体最小电压";
CM_ SG_ 2334387868 M2P_SysAvgVolt_B3_12 "汇流排3单体平均电压";
CM_ SG_ 2334387868 M2P_BMS_Status_B3 "汇流排3能量状态";
CM_ SG_ 2334387868 M2P_SOC_B3 "汇流排3系统SOC";
CM_ SG_ 2334387868 M2P_SOH_B3 "汇流排3系统SOH";
CM_ SG_ 2334387868 Reserved_12 "预留";
CM_ SG_ 2334387869 M2P_SysMinVolt_B3_13 "汇流排3单体最小电压";
CM_ SG_ 2334387869 M2P_SysAvgVolt_B3_13 "汇流排3单体平均电压";
CM_ SG_ 2334387869 M2P_BMS_Status_B3 "汇流排3能量状态";
CM_ SG_ 2334387869 M2P_SOC_B3 "汇流排3系统SOC";
CM_ SG_ 2334387869 M2P_SOH_B3 "汇流排3系统SOH";
CM_ SG_ 2334387869 Reserved_13 "预留";
CM_ SG_ 2334387870 M2P_SysMinVolt_B3_14 "汇流排3单体最小电压";
CM_ SG_ 2334387870 M2P_SysAvgVolt_B3_14 "汇流排3单体平均电压";
CM_ SG_ 2334387870 M2P_BMS_Status_B3 "汇流排3能量状态";
CM_ SG_ 2334387870 M2P_SOC_B3 "汇流排3系统SOC";
CM_ SG_ 2334387870 M2P_SOH_B3 "汇流排3系统SOH";
CM_ SG_ 2334387870 Reserved_14 "预留";
CM_ SG_ 2334387871 M2P_SysMinVolt_B3_15 "汇流排3单体最小电压";
CM_ SG_ 2334387871 M2P_SysAvgVolt_B3_15 "汇流排3单体平均电压";
CM_ SG_ 2334387871 M2P_BMS_Status_B3 "汇流排3能量状态";
CM_ SG_ 2334387871 M2P_SOC_B3 "汇流排3系统SOC";
CM_ SG_ 2334387871 M2P_SOH_B3 "汇流排3系统SOH";
CM_ SG_ 2334387871 Reserved_15 "预留";
CM_ SG_ 2334387872 M2P_SysMinVolt_B3_16 "汇流排3单体最小电压";
CM_ SG_ 2334387872 M2P_SysAvgVolt_B3_16 "汇流排3单体平均电压";
CM_ SG_ 2334387872 M2P_BMS_Status_B3 "汇流排3能量状态";
CM_ SG_ 2334387872 M2P_SOC_B3 "汇流排3系统SOC";
CM_ SG_ 2334387872 M2P_SOH_B3 "汇流排3系统SOH";
CM_ SG_ 2334387872 Reserved_16 "预留";
CM_ SG_ 2334387873 M2P_SysMinVolt_B3_17 "汇流排3单体最小电压";
CM_ SG_ 2334387873 M2P_SysAvgVolt_B3_17 "汇流排3单体平均电压";
CM_ SG_ 2334387873 M2P_BMS_Status_B3 "汇流排3能量状态";
CM_ SG_ 2334387873 M2P_SOC_B3 "汇流排3系统SOC";
CM_ SG_ 2334387873 M2P_SOH_B3 "汇流排3系统SOH";
CM_ SG_ 2334387873 Reserved_17 "预留";
CM_ SG_ 2334387874 M2P_SysMinVolt_B3_18 "汇流排3单体最小电压";
CM_ SG_ 2334387874 M2P_SysAvgVolt_B3_18 "汇流排3单体平均电压";
CM_ SG_ 2334387874 M2P_BMS_Status_B3 "汇流排3能量状态";
CM_ SG_ 2334387874 M2P_SOC_B3 "汇流排3系统SOC";
CM_ SG_ 2334387874 M2P_SOH_B3 "汇流排3系统SOH";
CM_ SG_ 2334387874 Reserved_18 "预留";
CM_ SG_ 2334387875 M2P_SysMinVolt_B3_19 "汇流排3单体最小电压";
CM_ SG_ 2334387875 M2P_SysAvgVolt_B3_19 "汇流排3单体平均电压";
CM_ SG_ 2334387875 M2P_BMS_Status_B3 "汇流排3能量状态";
CM_ SG_ 2334387875 M2P_SOC_B3 "汇流排3系统SOC";
CM_ SG_ 2334387875 M2P_SOH_B3 "汇流排3系统SOH";
CM_ SG_ 2334387875 Reserved_19 "预留";
CM_ SG_ 2334387876 M2P_SysMinVolt_B3_20 "汇流排3单体最小电压";
CM_ SG_ 2334387876 M2P_SysAvgVolt_B3_20 "汇流排3单体平均电压";
CM_ SG_ 2334387876 M2P_BMS_Status_B3 "汇流排3能量状态";
CM_ SG_ 2334387876 M2P_SOC_B3 "汇流排3系统SOC";
CM_ SG_ 2334387876 M2P_SOH_B3 "汇流排3系统SOH";
CM_ SG_ 2334387876 Reserved_20 "预留";
CM_ SG_ 2334387877 M2P_SysMinVolt_B3_21 "汇流排3单体最小电压";
CM_ SG_ 2334387877 M2P_SysAvgVolt_B3_21 "汇流排3单体平均电压";
CM_ SG_ 2334387877 M2P_BMS_Status_B3 "汇流排3能量状态";
CM_ SG_ 2334387877 M2P_SOC_B3 "汇流排3系统SOC";
CM_ SG_ 2334387877 M2P_SOH_B3 "汇流排3系统SOH";
CM_ SG_ 2334387877 Reserved_21 "预留";
CM_ SG_ 2334387878 M2P_SysMinVolt_B3_22 "汇流排3单体最小电压";
CM_ SG_ 2334387878 M2P_SysAvgVolt_B3_22 "汇流排3单体平均电压";
CM_ SG_ 2334387878 M2P_BMS_Status_B3 "汇流排3能量状态";
CM_ SG_ 2334387878 M2P_SOC_B3 "汇流排3系统SOC";
CM_ SG_ 2334387878 M2P_SOH_B3 "汇流排3系统SOH";
CM_ SG_ 2334387878 Reserved_22 "预留";
CM_ SG_ 2334387879 M2P_SysMinVolt_B3_23 "汇流排3单体最小电压";
CM_ SG_ 2334387879 M2P_SysAvgVolt_B3_23 "汇流排3单体平均电压";
CM_ SG_ 2334387879 M2P_BMS_Status_B3 "汇流排3能量状态";
CM_ SG_ 2334387879 M2P_SOC_B3 "汇流排3系统SOC";
CM_ SG_ 2334387879 M2P_SOH_B3 "汇流排3系统SOH";
CM_ SG_ 2334387879 Reserved_23 "预留";
CM_ SG_ 2334387880 M2P_SysMinVolt_B3_24 "汇流排3单体最小电压";
CM_ SG_ 2334387880 M2P_SysAvgVolt_B3_24 "汇流排3单体平均电压";
CM_ SG_ 2334387880 M2P_BMS_Status_B3 "汇流排3能量状态";
CM_ SG_ 2334387880 M2P_SOC_B3 "汇流排3系统SOC";
CM_ SG_ 2334387880 M2P_SOH_B3 "汇流排3系统SOH";
CM_ SG_ 2334387880 Reserved_24 "预留";
CM_ SG_ 2334387881 M2P_SysMinVolt_B3_25 "汇流排3单体最小电压";
CM_ SG_ 2334387881 M2P_SysAvgVolt_B3_25 "汇流排3单体平均电压";
CM_ SG_ 2334387881 M2P_BMS_Status_B3 "汇流排3能量状态";
CM_ SG_ 2334387881 M2P_SOC_B3 "汇流排3系统SOC";
CM_ SG_ 2334387881 M2P_SOH_B3 "汇流排3系统SOH";
CM_ SG_ 2334387881 Reserved_25 "预留";
CM_ SG_ 2334387882 M2P_SysMinVolt_B3_26 "汇流排3单体最小电压";
CM_ SG_ 2334387882 M2P_SysAvgVolt_B3_26 "汇流排3单体平均电压";
CM_ SG_ 2334387882 M2P_BMS_Status_B3 "汇流排3能量状态";
CM_ SG_ 2334387882 M2P_SOC_B3 "汇流排3系统SOC";
CM_ SG_ 2334387882 M2P_SOH_B3 "汇流排3系统SOH";
CM_ SG_ 2334387882 Reserved_26 "预留";
CM_ SG_ 2334387883 M2P_SysMinVolt_B3_27 "汇流排3单体最小电压";
CM_ SG_ 2334387883 M2P_SysAvgVolt_B3_27 "汇流排3单体平均电压";
CM_ SG_ 2334387883 M2P_BMS_Status_B3 "汇流排3能量状态";
CM_ SG_ 2334387883 M2P_SOC_B3 "汇流排3系统SOC";
CM_ SG_ 2334387883 M2P_SOH_B3 "汇流排3系统SOH";
CM_ SG_ 2334387883 Reserved_27 "预留";
CM_ SG_ 2334387884 M2P_SysMinVolt_B3_28 "汇流排3单体最小电压";
CM_ SG_ 2334387884 M2P_SysAvgVolt_B3_28 "汇流排3单体平均电压";
CM_ SG_ 2334387884 M2P_BMS_Status_B3 "汇流排3能量状态";
CM_ SG_ 2334387884 M2P_SOC_B3 "汇流排3系统SOC";
CM_ SG_ 2334387884 M2P_SOH_B3 "汇流排3系统SOH";
CM_ SG_ 2334387884 Reserved_28 "预留";
CM_ SG_ 2334387885 M2P_SysMinVolt_B3_29 "汇流排3单体最小电压";
CM_ SG_ 2334387885 M2P_SysAvgVolt_B3_29 "汇流排3单体平均电压";
CM_ SG_ 2334387885 M2P_BMS_Status_B3 "汇流排3能量状态";
CM_ SG_ 2334387885 M2P_SOC_B3 "汇流排3系统SOC";
CM_ SG_ 2334387885 M2P_SOH_B3 "汇流排3系统SOH";
CM_ SG_ 2334387885 Reserved_29 "预留";
CM_ SG_ 2334387886 M2P_SysMinVolt_B3_30 "汇流排3单体最小电压";
CM_ SG_ 2334387886 M2P_SysAvgVolt_B3_30 "汇流排3单体平均电压";
CM_ SG_ 2334387886 M2P_BMS_Status_B3 "汇流排3能量状态";
CM_ SG_ 2334387886 M2P_SOC_B3 "汇流排3系统SOC";
CM_ SG_ 2334387886 M2P_SOH_B3 "汇流排3系统SOH";
CM_ SG_ 2334387886 Reserved_30 "预留";
CM_ SG_ 2334387887 M2P_SysMinVolt_B3_31 "汇流排3单体最小电压";
CM_ SG_ 2334387887 M2P_SysAvgVolt_B3_31 "汇流排3单体平均电压";
CM_ SG_ 2334387887 M2P_BMS_Status_B3 "汇流排3能量状态";
CM_ SG_ 2334387887 M2P_SOC_B3 "汇流排3系统SOC";
CM_ SG_ 2334387887 M2P_SOH_B3 "汇流排3系统SOH";
CM_ SG_ 2334387887 Reserved_31 "预留";
CM_ SG_ 2334453393 M2P_SOE_Charge_B3 "汇流排3系可充电SOE";
CM_ SG_ 2334453393 M2P_SOE_Discharge_B3 "汇流排3系可放电SOE";
CM_ SG_ 2334453393 Reserved_01 "预留";
CM_ SG_ 2334453394 M2P_SOE_Charge_B3 "汇流排3系可充电SOE";
CM_ SG_ 2334453394 M2P_SOE_Discharge_B3 "汇流排3系可放电SOE";
CM_ SG_ 2334453394 Reserved_02 "预留";
CM_ SG_ 2334453395 M2P_SOE_Charge_B3 "汇流排3系可充电SOE";
CM_ SG_ 2334453395 M2P_SOE_Discharge_B3 "汇流排3系可放电SOE";
CM_ SG_ 2334453395 Reserved_03 "预留";
CM_ SG_ 2334453396 M2P_SOE_Charge_B3 "汇流排3系可充电SOE";
CM_ SG_ 2334453396 M2P_SOE_Discharge_B3 "汇流排3系可放电SOE";
CM_ SG_ 2334453396 Reserved_04 "预留";
CM_ SG_ 2334453397 M2P_SOE_Charge_B3 "汇流排3系可充电SOE";
CM_ SG_ 2334453397 M2P_SOE_Discharge_B3 "汇流排3系可放电SOE";
CM_ SG_ 2334453397 Reserved_05 "预留";
CM_ SG_ 2334453398 M2P_SOE_Charge_B3 "汇流排3系可充电SOE";
CM_ SG_ 2334453398 M2P_SOE_Discharge_B3 "汇流排3系可放电SOE";
CM_ SG_ 2334453398 Reserved_06 "预留";
CM_ SG_ 2334453399 M2P_SOE_Charge_B3 "汇流排3系可充电SOE";
CM_ SG_ 2334453399 M2P_SOE_Discharge_B3 "汇流排3系可放电SOE";
CM_ SG_ 2334453399 Reserved_07 "预留";
CM_ SG_ 2334453400 M2P_SOE_Charge_B3 "汇流排3系可充电SOE";
CM_ SG_ 2334453400 M2P_SOE_Discharge_B3 "汇流排3系可放电SOE";
CM_ SG_ 2334453400 Reserved_08 "预留";
CM_ SG_ 2334453401 M2P_SOE_Charge_B3 "汇流排3系可充电SOE";
CM_ SG_ 2334453401 M2P_SOE_Discharge_B3 "汇流排3系可放电SOE";
CM_ SG_ 2334453401 Reserved_09 "预留";
CM_ SG_ 2334453402 M2P_SOE_Charge_B3 "汇流排3系可充电SOE";
CM_ SG_ 2334453402 M2P_SOE_Discharge_B3 "汇流排3系可放电SOE";
CM_ SG_ 2334453402 Reserved_10 "预留";
CM_ SG_ 2334453403 M2P_SOE_Charge_B3 "汇流排3系可充电SOE";
CM_ SG_ 2334453403 M2P_SOE_Discharge_B3 "汇流排3系可放电SOE";
CM_ SG_ 2334453403 Reserved_11 "预留";
CM_ SG_ 2334453404 M2P_SOE_Charge_B3 "汇流排3系可充电SOE";
CM_ SG_ 2334453404 M2P_SOE_Discharge_B3 "汇流排3系可放电SOE";
CM_ SG_ 2334453404 Reserved_12 "预留";
CM_ SG_ 2334453405 M2P_SOE_Charge_B3 "汇流排3系可充电SOE";
CM_ SG_ 2334453405 M2P_SOE_Discharge_B3 "汇流排3系可放电SOE";
CM_ SG_ 2334453405 Reserved_13 "预留";
CM_ SG_ 2334453406 M2P_SOE_Charge_B3 "汇流排3系可充电SOE";
CM_ SG_ 2334453406 M2P_SOE_Discharge_B3 "汇流排3系可放电SOE";
CM_ SG_ 2334453406 Reserved_14 "预留";
CM_ SG_ 2334453407 M2P_SOE_Charge_B3 "汇流排3系可充电SOE";
CM_ SG_ 2334453407 M2P_SOE_Discharge_B3 "汇流排3系可放电SOE";
CM_ SG_ 2334453407 Reserved_15 "预留";
CM_ SG_ 2334453408 M2P_SOE_Charge_B3 "汇流排3系可充电SOE";
CM_ SG_ 2334453408 M2P_SOE_Discharge_B3 "汇流排3系可放电SOE";
CM_ SG_ 2334453408 Reserved_16 "预留";
CM_ SG_ 2334453409 M2P_SOE_Charge_B3 "汇流排3系可充电SOE";
CM_ SG_ 2334453409 M2P_SOE_Discharge_B3 "汇流排3系可放电SOE";
CM_ SG_ 2334453409 Reserved_17 "预留";
CM_ SG_ 2334453410 M2P_SOE_Charge_B3 "汇流排3系可充电SOE";
CM_ SG_ 2334453410 M2P_SOE_Discharge_B3 "汇流排3系可放电SOE";
CM_ SG_ 2334453410 Reserved_18 "预留";
CM_ SG_ 2334453411 M2P_SOE_Charge_B3 "汇流排3系可充电SOE";
CM_ SG_ 2334453411 M2P_SOE_Discharge_B3 "汇流排3系可放电SOE";
CM_ SG_ 2334453411 Reserved_19 "预留";
CM_ SG_ 2334453412 M2P_SOE_Charge_B3 "汇流排3系可充电SOE";
CM_ SG_ 2334453412 M2P_SOE_Discharge_B3 "汇流排3系可放电SOE";
CM_ SG_ 2334453412 Reserved_20 "预留";
CM_ SG_ 2334453413 M2P_SOE_Charge_B3 "汇流排3系可充电SOE";
CM_ SG_ 2334453413 M2P_SOE_Discharge_B3 "汇流排3系可放电SOE";
CM_ SG_ 2334453413 Reserved_21 "预留";
CM_ SG_ 2334453414 M2P_SOE_Charge_B3 "汇流排3系可充电SOE";
CM_ SG_ 2334453414 M2P_SOE_Discharge_B3 "汇流排3系可放电SOE";
CM_ SG_ 2334453414 Reserved_22 "预留";
CM_ SG_ 2334453415 M2P_SOE_Charge_B3 "汇流排3系可充电SOE";
CM_ SG_ 2334453415 M2P_SOE_Discharge_B3 "汇流排3系可放电SOE";
CM_ SG_ 2334453415 Reserved_23 "预留";
CM_ SG_ 2334453416 M2P_SOE_Charge_B3 "汇流排3系可充电SOE";
CM_ SG_ 2334453416 M2P_SOE_Discharge_B3 "汇流排3系可放电SOE";
CM_ SG_ 2334453416 Reserved_24 "预留";
CM_ SG_ 2334453417 M2P_SOE_Charge_B3 "汇流排3系可充电SOE";
CM_ SG_ 2334453417 M2P_SOE_Discharge_B3 "汇流排3系可放电SOE";
CM_ SG_ 2334453417 Reserved_25 "预留";
CM_ SG_ 2334453418 M2P_SOE_Charge_B3 "汇流排3系可充电SOE";
CM_ SG_ 2334453418 M2P_SOE_Discharge_B3 "汇流排3系可放电SOE";
CM_ SG_ 2334453418 Reserved_26 "预留";
CM_ SG_ 2334453419 M2P_SOE_Charge_B3 "汇流排3系可充电SOE";
CM_ SG_ 2334453419 M2P_SOE_Discharge_B3 "汇流排3系可放电SOE";
CM_ SG_ 2334453419 Reserved_27 "预留";
CM_ SG_ 2334453420 M2P_SOE_Charge_B3 "汇流排3系可充电SOE";
CM_ SG_ 2334453420 M2P_SOE_Discharge_B3 "汇流排3系可放电SOE";
CM_ SG_ 2334453420 Reserved_28 "预留";
CM_ SG_ 2334453421 M2P_SOE_Charge_B3 "汇流排3系可充电SOE";
CM_ SG_ 2334453421 M2P_SOE_Discharge_B3 "汇流排3系可放电SOE";
CM_ SG_ 2334453421 Reserved_29 "预留";
CM_ SG_ 2334453422 M2P_SOE_Charge_B3 "汇流排3系可充电SOE";
CM_ SG_ 2334453422 M2P_SOE_Discharge_B3 "汇流排3系可放电SOE";
CM_ SG_ 2334453422 Reserved_30 "预留";
CM_ SG_ 2334453423 M2P_SOE_Charge_B3 "汇流排3系可充电SOE";
CM_ SG_ 2334453423 M2P_SOE_Discharge_B3 "汇流排3系可放电SOE";
CM_ SG_ 2334453423 Reserved_31 "预留";
CM_ SG_ 2334518929 M2P_Measure_Vol_B4_01 "汇流排4所有高压在线电柜外侧电压平均值    ";
CM_ SG_ 2334518929 M2P_Current_B4_01 "汇流排4所有电柜电流累加和";
CM_ SG_ 2334518929 M2P_PermitMaxCharge_I_B4_01 "汇流排4最大允许充电电流";
CM_ SG_ 2334518929 M2P_PermitMaxDisCharge_I_B4_01 "汇流排4最大允许放电电流";
CM_ SG_ 2334518930 M2P_Measure_Vol_B4_02 "汇流排4所有高压在线电柜外侧电压平均值    ";
CM_ SG_ 2334518930 M2P_Current_B4_02 "汇流排4所有电柜电流累加和";
CM_ SG_ 2334518930 M2P_PermitMaxCharge_I_B4_02 "汇流排4最大允许充电电流";
CM_ SG_ 2334518930 M2P_PermitMaxDisCharge_I_B4_02 "汇流排4最大允许放电电流";
CM_ SG_ 2334518931 M2P_Measure_Vol_B4_03 "汇流排4所有高压在线电柜外侧电压平均值    ";
CM_ SG_ 2334518931 M2P_Current_B4_03 "汇流排4所有电柜电流累加和";
CM_ SG_ 2334518931 M2P_PermitMaxCharge_I_B4_03 "汇流排4最大允许充电电流";
CM_ SG_ 2334518931 M2P_PermitMaxDisCharge_I_B4_03 "汇流排4最大允许放电电流";
CM_ SG_ 2334518932 M2P_Measure_Vol_B4_04 "汇流排4所有高压在线电柜外侧电压平均值    ";
CM_ SG_ 2334518932 M2P_Current_B4_04 "汇流排4所有电柜电流累加和";
CM_ SG_ 2334518932 M2P_PermitMaxCharge_I_B4_04 "汇流排4最大允许充电电流";
CM_ SG_ 2334518932 M2P_PermitMaxDisCharge_I_B4_04 "汇流排4最大允许放电电流";
CM_ SG_ 2334518933 M2P_Measure_Vol_B4_05 "汇流排4所有高压在线电柜外侧电压平均值    ";
CM_ SG_ 2334518933 M2P_Current_B4_05 "汇流排4所有电柜电流累加和";
CM_ SG_ 2334518933 M2P_PermitMaxCharge_I_B4_05 "汇流排4最大允许充电电流";
CM_ SG_ 2334518933 M2P_PermitMaxDisCharge_I_B4_05 "汇流排4最大允许放电电流";
CM_ SG_ 2334518934 M2P_Measure_Vol_B4_06 "汇流排4所有高压在线电柜外侧电压平均值    ";
CM_ SG_ 2334518934 M2P_Current_B4_06 "汇流排4所有电柜电流累加和";
CM_ SG_ 2334518934 M2P_PermitMaxCharge_I_B4_06 "汇流排4最大允许充电电流";
CM_ SG_ 2334518934 M2P_PermitMaxDisCharge_I_B4_06 "汇流排4最大允许放电电流";
CM_ SG_ 2334518935 M2P_Measure_Vol_B4_07 "汇流排4所有高压在线电柜外侧电压平均值    ";
CM_ SG_ 2334518935 M2P_Current_B4_07 "汇流排4所有电柜电流累加和";
CM_ SG_ 2334518935 M2P_PermitMaxCharge_I_B4_07 "汇流排4最大允许充电电流";
CM_ SG_ 2334518935 M2P_PermitMaxDisCharge_I_B4_07 "汇流排4最大允许放电电流";
CM_ SG_ 2334518936 M2P_Measure_Vol_B4_08 "汇流排4所有高压在线电柜外侧电压平均值    ";
CM_ SG_ 2334518936 M2P_Current_B4_08 "汇流排4所有电柜电流累加和";
CM_ SG_ 2334518936 M2P_PermitMaxCharge_I_B4_08 "汇流排4最大允许充电电流";
CM_ SG_ 2334518936 M2P_PermitMaxDisCharge_I_B4_08 "汇流排4最大允许放电电流";
CM_ SG_ 2334518937 M2P_Measure_Vol_B4_09 "汇流排4所有高压在线电柜外侧电压平均值    ";
CM_ SG_ 2334518937 M2P_Current_B4_09 "汇流排4所有电柜电流累加和";
CM_ SG_ 2334518937 M2P_PermitMaxCharge_I_B4_09 "汇流排4最大允许充电电流";
CM_ SG_ 2334518937 M2P_PermitMaxDisCharge_I_B4_09 "汇流排4最大允许放电电流";
CM_ SG_ 2334518938 M2P_Measure_Vol_B4_10 "汇流排4所有高压在线电柜外侧电压平均值    ";
CM_ SG_ 2334518938 M2P_Current_B4_10 "汇流排4所有电柜电流累加和";
CM_ SG_ 2334518938 M2P_PermitMaxCharge_I_B4_10 "汇流排4最大允许充电电流";
CM_ SG_ 2334518938 M2P_PermitMaxDisCharge_I_B4_10 "汇流排4最大允许放电电流";
CM_ SG_ 2334518939 M2P_Measure_Vol_B4_11 "汇流排4所有高压在线电柜外侧电压平均值    ";
CM_ SG_ 2334518939 M2P_Current_B4_11 "汇流排4所有电柜电流累加和";
CM_ SG_ 2334518939 M2P_PermitMaxCharge_I_B4_11 "汇流排4最大允许充电电流";
CM_ SG_ 2334518939 M2P_PermitMaxDisCharge_I_B4_11 "汇流排4最大允许放电电流";
CM_ SG_ 2334518940 M2P_Measure_Vol_B4_12 "汇流排4所有高压在线电柜外侧电压平均值    ";
CM_ SG_ 2334518940 M2P_Current_B4_12 "汇流排4所有电柜电流累加和";
CM_ SG_ 2334518940 M2P_PermitMaxCharge_I_B4_12 "汇流排4最大允许充电电流";
CM_ SG_ 2334518940 M2P_PermitMaxDisCharge_I_B4_12 "汇流排4最大允许放电电流";
CM_ SG_ 2334518941 M2P_Measure_Vol_B4_13 "汇流排4所有高压在线电柜外侧电压平均值    ";
CM_ SG_ 2334518941 M2P_Current_B4_13 "汇流排4所有电柜电流累加和";
CM_ SG_ 2334518941 M2P_PermitMaxCharge_I_B4_13 "汇流排4最大允许充电电流";
CM_ SG_ 2334518941 M2P_PermitMaxDisCharge_I_B4_13 "汇流排4最大允许放电电流";
CM_ SG_ 2334518942 M2P_Measure_Vol_B4_14 "汇流排4所有高压在线电柜外侧电压平均值    ";
CM_ SG_ 2334518942 M2P_Current_B4_14 "汇流排4所有电柜电流累加和";
CM_ SG_ 2334518942 M2P_PermitMaxCharge_I_B4_14 "汇流排4最大允许充电电流";
CM_ SG_ 2334518942 M2P_PermitMaxDisCharge_I_B4_14 "汇流排4最大允许放电电流";
CM_ SG_ 2334518943 M2P_Measure_Vol_B4_15 "汇流排4所有高压在线电柜外侧电压平均值    ";
CM_ SG_ 2334518943 M2P_Current_B4_15 "汇流排4所有电柜电流累加和";
CM_ SG_ 2334518943 M2P_PermitMaxCharge_I_B4_15 "汇流排4最大允许充电电流";
CM_ SG_ 2334518943 M2P_PermitMaxDisCharge_I_B4_15 "汇流排4最大允许放电电流";
CM_ SG_ 2334518944 M2P_Measure_Vol_B4_16 "汇流排4所有高压在线电柜外侧电压平均值    ";
CM_ SG_ 2334518944 M2P_Current_B4_16 "汇流排4所有电柜电流累加和";
CM_ SG_ 2334518944 M2P_PermitMaxCharge_I_B4_16 "汇流排4最大允许充电电流";
CM_ SG_ 2334518944 M2P_PermitMaxDisCharge_I_B4_16 "汇流排4最大允许放电电流";
CM_ SG_ 2334518945 M2P_Measure_Vol_B4_17 "汇流排4所有高压在线电柜外侧电压平均值    ";
CM_ SG_ 2334518945 M2P_Current_B4_17 "汇流排4所有电柜电流累加和";
CM_ SG_ 2334518945 M2P_PermitMaxCharge_I_B4_17 "汇流排4最大允许充电电流";
CM_ SG_ 2334518945 M2P_PermitMaxDisCharge_I_B4_17 "汇流排4最大允许放电电流";
CM_ SG_ 2334518946 M2P_Measure_Vol_B4_18 "汇流排4所有高压在线电柜外侧电压平均值    ";
CM_ SG_ 2334518946 M2P_Current_B4_18 "汇流排4所有电柜电流累加和";
CM_ SG_ 2334518946 M2P_PermitMaxCharge_I_B4_18 "汇流排4最大允许充电电流";
CM_ SG_ 2334518946 M2P_PermitMaxDisCharge_I_B4_18 "汇流排4最大允许放电电流";
CM_ SG_ 2334518947 M2P_Measure_Vol_B4_19 "汇流排4所有高压在线电柜外侧电压平均值    ";
CM_ SG_ 2334518947 M2P_Current_B4_19 "汇流排4所有电柜电流累加和";
CM_ SG_ 2334518947 M2P_PermitMaxCharge_I_B4_19 "汇流排4最大允许充电电流";
CM_ SG_ 2334518947 M2P_PermitMaxDisCharge_I_B4_19 "汇流排4最大允许放电电流";
CM_ SG_ 2334518948 M2P_Measure_Vol_B4_20 "汇流排4所有高压在线电柜外侧电压平均值    ";
CM_ SG_ 2334518948 M2P_Current_B4_20 "汇流排4所有电柜电流累加和";
CM_ SG_ 2334518948 M2P_PermitMaxCharge_I_B4_20 "汇流排4最大允许充电电流";
CM_ SG_ 2334518948 M2P_PermitMaxDisCharge_I_B4_20 "汇流排4最大允许放电电流";
CM_ SG_ 2334518949 M2P_Measure_Vol_B4_21 "汇流排4所有高压在线电柜外侧电压平均值    ";
CM_ SG_ 2334518949 M2P_Current_B4_21 "汇流排4所有电柜电流累加和";
CM_ SG_ 2334518949 M2P_PermitMaxCharge_I_B4_21 "汇流排4最大允许充电电流";
CM_ SG_ 2334518949 M2P_PermitMaxDisCharge_I_B4_21 "汇流排4最大允许放电电流";
CM_ SG_ 2334518950 M2P_Measure_Vol_B4_22 "汇流排4所有高压在线电柜外侧电压平均值    ";
CM_ SG_ 2334518950 M2P_Current_B4_22 "汇流排4所有电柜电流累加和";
CM_ SG_ 2334518950 M2P_PermitMaxCharge_I_B4_22 "汇流排4最大允许充电电流";
CM_ SG_ 2334518950 M2P_PermitMaxDisCharge_I_B4_22 "汇流排4最大允许放电电流";
CM_ SG_ 2334518951 M2P_Measure_Vol_B4_23 "汇流排4所有高压在线电柜外侧电压平均值    ";
CM_ SG_ 2334518951 M2P_Current_B4_23 "汇流排4所有电柜电流累加和";
CM_ SG_ 2334518951 M2P_PermitMaxCharge_I_B4_23 "汇流排4最大允许充电电流";
CM_ SG_ 2334518951 M2P_PermitMaxDisCharge_I_B4_23 "汇流排4最大允许放电电流";
CM_ SG_ 2334518952 M2P_Measure_Vol_B4_24 "汇流排4所有高压在线电柜外侧电压平均值    ";
CM_ SG_ 2334518952 M2P_Current_B4_24 "汇流排4所有电柜电流累加和";
CM_ SG_ 2334518952 M2P_PermitMaxCharge_I_B4_24 "汇流排4最大允许充电电流";
CM_ SG_ 2334518952 M2P_PermitMaxDisCharge_I_B4_24 "汇流排4最大允许放电电流";
CM_ SG_ 2334518953 M2P_Measure_Vol_B4_25 "汇流排4所有高压在线电柜外侧电压平均值    ";
CM_ SG_ 2334518953 M2P_Current_B4_25 "汇流排4所有电柜电流累加和";
CM_ SG_ 2334518953 M2P_PermitMaxCharge_I_B4_25 "汇流排4最大允许充电电流";
CM_ SG_ 2334518953 M2P_PermitMaxDisCharge_I_B4_25 "汇流排4最大允许放电电流";
CM_ SG_ 2334518954 M2P_Measure_Vol_B4_26 "汇流排4所有高压在线电柜外侧电压平均值    ";
CM_ SG_ 2334518954 M2P_Current_B4_26 "汇流排4所有电柜电流累加和";
CM_ SG_ 2334518954 M2P_PermitMaxCharge_I_B4_26 "汇流排4最大允许充电电流";
CM_ SG_ 2334518954 M2P_PermitMaxDisCharge_I_B4_26 "汇流排4最大允许放电电流";
CM_ SG_ 2334518955 M2P_Measure_Vol_B4_27 "汇流排4所有高压在线电柜外侧电压平均值    ";
CM_ SG_ 2334518955 M2P_Current_B4_27 "汇流排4所有电柜电流累加和";
CM_ SG_ 2334518955 M2P_PermitMaxCharge_I_B4_27 "汇流排4最大允许充电电流";
CM_ SG_ 2334518955 M2P_PermitMaxDisCharge_I_B4_27 "汇流排4最大允许放电电流";
CM_ SG_ 2334518956 M2P_Measure_Vol_B4_28 "汇流排4所有高压在线电柜外侧电压平均值    ";
CM_ SG_ 2334518956 M2P_Current_B4_28 "汇流排4所有电柜电流累加和";
CM_ SG_ 2334518956 M2P_PermitMaxCharge_I_B4_28 "汇流排4最大允许充电电流";
CM_ SG_ 2334518956 M2P_PermitMaxDisCharge_I_B4_28 "汇流排4最大允许放电电流";
CM_ SG_ 2334518957 M2P_Measure_Vol_B4_29 "汇流排4所有高压在线电柜外侧电压平均值    ";
CM_ SG_ 2334518957 M2P_Current_B4_29 "汇流排4所有电柜电流累加和";
CM_ SG_ 2334518957 M2P_PermitMaxCharge_I_B4_29 "汇流排4最大允许充电电流";
CM_ SG_ 2334518957 M2P_PermitMaxDisCharge_I_B4_29 "汇流排4最大允许放电电流";
CM_ SG_ 2334518958 M2P_Measure_Vol_B4_30 "汇流排4所有高压在线电柜外侧电压平均值    ";
CM_ SG_ 2334518958 M2P_Current_B4_30 "汇流排4所有电柜电流累加和";
CM_ SG_ 2334518958 M2P_PermitMaxCharge_I_B4_30 "汇流排4最大允许充电电流";
CM_ SG_ 2334518958 M2P_PermitMaxDisCharge_I_B4_30 "汇流排4最大允许放电电流";
CM_ SG_ 2334518959 M2P_Measure_Vol_B4_31 "汇流排4所有高压在线电柜外侧电压平均值    ";
CM_ SG_ 2334518959 M2P_Current_B4_31 "汇流排4所有电柜电流累加和";
CM_ SG_ 2334518959 M2P_PermitMaxCharge_I_B4_31 "汇流排4最大允许充电电流";
CM_ SG_ 2334518959 M2P_PermitMaxDisCharge_I_B4_31 "汇流排4最大允许放电电流";
CM_ SG_ 2334584465 M2P_PermitMaxVolt_B4_01 "汇流排4最高允许充电电压 （配置量）";
CM_ SG_ 2334584465 M2P_PermitMinVolt_B4_01 "汇流排4最低允许放电电压 （配置量）";
CM_ SG_ 2334584465 M2P_PermitMaxPow_Chg_B4_01 "汇流排4最大允许充电功率";
CM_ SG_ 2334584465 M2P_PermitMaxPow_DisChg_B4_01 "汇流排4最大允许放电功率";
CM_ SG_ 2334584466 M2P_PermitMaxVolt_B4_02 "汇流排4最高允许充电电压 （配置量）";
CM_ SG_ 2334584466 M2P_PermitMinVolt_B4_02 "汇流排4最低允许放电电压 （配置量）";
CM_ SG_ 2334584466 M2P_PermitMaxPow_Chg_B4_02 "汇流排4最大允许充电功率";
CM_ SG_ 2334584466 M2P_PermitMaxPow_DisChg_B4_02 "汇流排4最大允许放电功率";
CM_ SG_ 2334584467 M2P_PermitMaxVolt_B4_03 "汇流排4最高允许充电电压 （配置量）";
CM_ SG_ 2334584467 M2P_PermitMinVolt_B4_03 "汇流排4最低允许放电电压 （配置量）";
CM_ SG_ 2334584467 M2P_PermitMaxPow_Chg_B4_03 "汇流排4最大允许充电功率";
CM_ SG_ 2334584467 M2P_PermitMaxPow_DisChg_B4_03 "汇流排4最大允许放电功率";
CM_ SG_ 2334584468 M2P_PermitMaxVolt_B4_04 "汇流排4最高允许充电电压 （配置量）";
CM_ SG_ 2334584468 M2P_PermitMinVolt_B4_04 "汇流排4最低允许放电电压 （配置量）";
CM_ SG_ 2334584468 M2P_PermitMaxPow_Chg_B4_04 "汇流排4最大允许充电功率";
CM_ SG_ 2334584468 M2P_PermitMaxPow_DisChg_B4_04 "汇流排4最大允许放电功率";
CM_ SG_ 2334584469 M2P_PermitMaxVolt_B4_05 "汇流排4最高允许充电电压 （配置量）";
CM_ SG_ 2334584469 M2P_PermitMinVolt_B4_05 "汇流排4最低允许放电电压 （配置量）";
CM_ SG_ 2334584469 M2P_PermitMaxPow_Chg_B4_05 "汇流排4最大允许充电功率";
CM_ SG_ 2334584469 M2P_PermitMaxPow_DisChg_B4_05 "汇流排4最大允许放电功率";
CM_ SG_ 2334584470 M2P_PermitMaxVolt_B4_06 "汇流排4最高允许充电电压 （配置量）";
CM_ SG_ 2334584470 M2P_PermitMinVolt_B4_06 "汇流排4最低允许放电电压 （配置量）";
CM_ SG_ 2334584470 M2P_PermitMaxPow_Chg_B4_06 "汇流排4最大允许充电功率";
CM_ SG_ 2334584470 M2P_PermitMaxPow_DisChg_B4_06 "汇流排4最大允许放电功率";
CM_ SG_ 2334584471 M2P_PermitMaxVolt_B4_07 "汇流排4最高允许充电电压 （配置量）";
CM_ SG_ 2334584471 M2P_PermitMinVolt_B4_07 "汇流排4最低允许放电电压 （配置量）";
CM_ SG_ 2334584471 M2P_PermitMaxPow_Chg_B4_07 "汇流排4最大允许充电功率";
CM_ SG_ 2334584471 M2P_PermitMaxPow_DisChg_B4_07 "汇流排4最大允许放电功率";
CM_ SG_ 2334584472 M2P_PermitMaxVolt_B4_08 "汇流排4最高允许充电电压 （配置量）";
CM_ SG_ 2334584472 M2P_PermitMinVolt_B4_08 "汇流排4最低允许放电电压 （配置量）";
CM_ SG_ 2334584472 M2P_PermitMaxPow_Chg_B4_08 "汇流排4最大允许充电功率";
CM_ SG_ 2334584472 M2P_PermitMaxPow_DisChg_B4_08 "汇流排4最大允许放电功率";
CM_ SG_ 2334584473 M2P_PermitMaxVolt_B4_09 "汇流排4最高允许充电电压 （配置量）";
CM_ SG_ 2334584473 M2P_PermitMinVolt_B4_09 "汇流排4最低允许放电电压 （配置量）";
CM_ SG_ 2334584473 M2P_PermitMaxPow_Chg_B4_09 "汇流排4最大允许充电功率";
CM_ SG_ 2334584473 M2P_PermitMaxPow_DisChg_B4_09 "汇流排4最大允许放电功率";
CM_ SG_ 2334584474 M2P_PermitMaxVolt_B4_10 "汇流排4最高允许充电电压 （配置量）";
CM_ SG_ 2334584474 M2P_PermitMinVolt_B4_10 "汇流排4最低允许放电电压 （配置量）";
CM_ SG_ 2334584474 M2P_PermitMaxPow_Chg_B4_10 "汇流排4最大允许充电功率";
CM_ SG_ 2334584474 M2P_PermitMaxPow_DisChg_B4_10 "汇流排4最大允许放电功率";
CM_ SG_ 2334584475 M2P_PermitMaxVolt_B4_11 "汇流排4最高允许充电电压 （配置量）";
CM_ SG_ 2334584475 M2P_PermitMinVolt_B4_11 "汇流排4最低允许放电电压 （配置量）";
CM_ SG_ 2334584475 M2P_PermitMaxPow_Chg_B4_11 "汇流排4最大允许充电功率";
CM_ SG_ 2334584475 M2P_PermitMaxPow_DisChg_B4_11 "汇流排4最大允许放电功率";
CM_ SG_ 2334584476 M2P_PermitMaxVolt_B4_12 "汇流排4最高允许充电电压 （配置量）";
CM_ SG_ 2334584476 M2P_PermitMinVolt_B4_12 "汇流排4最低允许放电电压 （配置量）";
CM_ SG_ 2334584476 M2P_PermitMaxPow_Chg_B4_12 "汇流排4最大允许充电功率";
CM_ SG_ 2334584476 M2P_PermitMaxPow_DisChg_B4_12 "汇流排4最大允许放电功率";
CM_ SG_ 2334584477 M2P_PermitMaxVolt_B4_13 "汇流排4最高允许充电电压 （配置量）";
CM_ SG_ 2334584477 M2P_PermitMinVolt_B4_13 "汇流排4最低允许放电电压 （配置量）";
CM_ SG_ 2334584477 M2P_PermitMaxPow_Chg_B4_13 "汇流排4最大允许充电功率";
CM_ SG_ 2334584477 M2P_PermitMaxPow_DisChg_B4_13 "汇流排4最大允许放电功率";
CM_ SG_ 2334584478 M2P_PermitMaxVolt_B4_14 "汇流排4最高允许充电电压 （配置量）";
CM_ SG_ 2334584478 M2P_PermitMinVolt_B4_14 "汇流排4最低允许放电电压 （配置量）";
CM_ SG_ 2334584478 M2P_PermitMaxPow_Chg_B4_14 "汇流排4最大允许充电功率";
CM_ SG_ 2334584478 M2P_PermitMaxPow_DisChg_B4_14 "汇流排4最大允许放电功率";
CM_ SG_ 2334584479 M2P_PermitMaxVolt_B4_15 "汇流排4最高允许充电电压 （配置量）";
CM_ SG_ 2334584479 M2P_PermitMinVolt_B4_15 "汇流排4最低允许放电电压 （配置量）";
CM_ SG_ 2334584479 M2P_PermitMaxPow_Chg_B4_15 "汇流排4最大允许充电功率";
CM_ SG_ 2334584479 M2P_PermitMaxPow_DisChg_B4_15 "汇流排4最大允许放电功率";
CM_ SG_ 2334584480 M2P_PermitMaxVolt_B4_16 "汇流排4最高允许充电电压 （配置量）";
CM_ SG_ 2334584480 M2P_PermitMinVolt_B4_16 "汇流排4最低允许放电电压 （配置量）";
CM_ SG_ 2334584480 M2P_PermitMaxPow_Chg_B4_16 "汇流排4最大允许充电功率";
CM_ SG_ 2334584480 M2P_PermitMaxPow_DisChg_B4_16 "汇流排4最大允许放电功率";
CM_ SG_ 2334584481 M2P_PermitMaxVolt_B4_17 "汇流排4最高允许充电电压 （配置量）";
CM_ SG_ 2334584481 M2P_PermitMinVolt_B4_17 "汇流排4最低允许放电电压 （配置量）";
CM_ SG_ 2334584481 M2P_PermitMaxPow_Chg_B4_17 "汇流排4最大允许充电功率";
CM_ SG_ 2334584481 M2P_PermitMaxPow_DisChg_B4_17 "汇流排4最大允许放电功率";
CM_ SG_ 2334584482 M2P_PermitMaxVolt_B4_18 "汇流排4最高允许充电电压 （配置量）";
CM_ SG_ 2334584482 M2P_PermitMinVolt_B4_18 "汇流排4最低允许放电电压 （配置量）";
CM_ SG_ 2334584482 M2P_PermitMaxPow_Chg_B4_18 "汇流排4最大允许充电功率";
CM_ SG_ 2334584482 M2P_PermitMaxPow_DisChg_B4_18 "汇流排4最大允许放电功率";
CM_ SG_ 2334584483 M2P_PermitMaxVolt_B4_19 "汇流排4最高允许充电电压 （配置量）";
CM_ SG_ 2334584483 M2P_PermitMinVolt_B4_19 "汇流排4最低允许放电电压 （配置量）";
CM_ SG_ 2334584483 M2P_PermitMaxPow_Chg_B4_19 "汇流排4最大允许充电功率";
CM_ SG_ 2334584483 M2P_PermitMaxPow_DisChg_B4_19 "汇流排4最大允许放电功率";
CM_ SG_ 2334584484 M2P_PermitMaxVolt_B4_20 "汇流排4最高允许充电电压 （配置量）";
CM_ SG_ 2334584484 M2P_PermitMinVolt_B4_20 "汇流排4最低允许放电电压 （配置量）";
CM_ SG_ 2334584484 M2P_PermitMaxPow_Chg_B4_20 "汇流排4最大允许充电功率";
CM_ SG_ 2334584484 M2P_PermitMaxPow_DisChg_B4_20 "汇流排4最大允许放电功率";
CM_ SG_ 2334584485 M2P_PermitMaxVolt_B4_21 "汇流排4最高允许充电电压 （配置量）";
CM_ SG_ 2334584485 M2P_PermitMinVolt_B4_21 "汇流排4最低允许放电电压 （配置量）";
CM_ SG_ 2334584485 M2P_PermitMaxPow_Chg_B4_21 "汇流排4最大允许充电功率";
CM_ SG_ 2334584485 M2P_PermitMaxPow_DisChg_B4_21 "汇流排4最大允许放电功率";
CM_ SG_ 2334584486 M2P_PermitMaxVolt_B4_22 "汇流排4最高允许充电电压 （配置量）";
CM_ SG_ 2334584486 M2P_PermitMinVolt_B4_22 "汇流排4最低允许放电电压 （配置量）";
CM_ SG_ 2334584486 M2P_PermitMaxPow_Chg_B4_22 "汇流排4最大允许充电功率";
CM_ SG_ 2334584486 M2P_PermitMaxPow_DisChg_B4_22 "汇流排4最大允许放电功率";
CM_ SG_ 2334584487 M2P_PermitMaxVolt_B4_23 "汇流排4最高允许充电电压 （配置量）";
CM_ SG_ 2334584487 M2P_PermitMinVolt_B4_23 "汇流排4最低允许放电电压 （配置量）";
CM_ SG_ 2334584487 M2P_PermitMaxPow_Chg_B4_23 "汇流排4最大允许充电功率";
CM_ SG_ 2334584487 M2P_PermitMaxPow_DisChg_B4_23 "汇流排4最大允许放电功率";
CM_ SG_ 2334584488 M2P_PermitMaxVolt_B4_24 "汇流排4最高允许充电电压 （配置量）";
CM_ SG_ 2334584488 M2P_PermitMinVolt_B4_24 "汇流排4最低允许放电电压 （配置量）";
CM_ SG_ 2334584488 M2P_PermitMaxPow_Chg_B4_24 "汇流排4最大允许充电功率";
CM_ SG_ 2334584488 M2P_PermitMaxPow_DisChg_B4_24 "汇流排4最大允许放电功率";
CM_ SG_ 2334584489 M2P_PermitMaxVolt_B4_25 "汇流排4最高允许充电电压 （配置量）";
CM_ SG_ 2334584489 M2P_PermitMinVolt_B4_25 "汇流排4最低允许放电电压 （配置量）";
CM_ SG_ 2334584489 M2P_PermitMaxPow_Chg_B4_25 "汇流排4最大允许充电功率";
CM_ SG_ 2334584489 M2P_PermitMaxPow_DisChg_B4_25 "汇流排4最大允许放电功率";
CM_ SG_ 2334584490 M2P_PermitMaxVolt_B4_26 "汇流排4最高允许充电电压 （配置量）";
CM_ SG_ 2334584490 M2P_PermitMinVolt_B4_26 "汇流排4最低允许放电电压 （配置量）";
CM_ SG_ 2334584490 M2P_PermitMaxPow_Chg_B4_26 "汇流排4最大允许充电功率";
CM_ SG_ 2334584490 M2P_PermitMaxPow_DisChg_B4_26 "汇流排4最大允许放电功率";
CM_ SG_ 2334584491 M2P_PermitMaxVolt_B4_27 "汇流排4最高允许充电电压 （配置量）";
CM_ SG_ 2334584491 M2P_PermitMinVolt_B4_27 "汇流排4最低允许放电电压 （配置量）";
CM_ SG_ 2334584491 M2P_PermitMaxPow_Chg_B4_27 "汇流排4最大允许充电功率";
CM_ SG_ 2334584491 M2P_PermitMaxPow_DisChg_B4_27 "汇流排4最大允许放电功率";
CM_ SG_ 2334584492 M2P_PermitMaxVolt_B4_28 "汇流排4最高允许充电电压 （配置量）";
CM_ SG_ 2334584492 M2P_PermitMinVolt_B4_28 "汇流排4最低允许放电电压 （配置量）";
CM_ SG_ 2334584492 M2P_PermitMaxPow_Chg_B4_28 "汇流排4最大允许充电功率";
CM_ SG_ 2334584492 M2P_PermitMaxPow_DisChg_B4_28 "汇流排4最大允许放电功率";
CM_ SG_ 2334584493 M2P_PermitMaxVolt_B4_29 "汇流排4最高允许充电电压 （配置量）";
CM_ SG_ 2334584493 M2P_PermitMinVolt_B4_29 "汇流排4最低允许放电电压 （配置量）";
CM_ SG_ 2334584493 M2P_PermitMaxPow_Chg_B4_29 "汇流排4最大允许充电功率";
CM_ SG_ 2334584493 M2P_PermitMaxPow_DisChg_B4_29 "汇流排4最大允许放电功率";
CM_ SG_ 2334584494 M2P_PermitMaxVolt_B4_30 "汇流排4最高允许充电电压 （配置量）";
CM_ SG_ 2334584494 M2P_PermitMinVolt_B4_30 "汇流排4最低允许放电电压 （配置量）";
CM_ SG_ 2334584494 M2P_PermitMaxPow_Chg_B4_30 "汇流排4最大允许充电功率";
CM_ SG_ 2334584494 M2P_PermitMaxPow_DisChg_B4_30 "汇流排4最大允许放电功率";
CM_ SG_ 2334584495 M2P_PermitMaxVolt_B4_31 "汇流排4最高允许充电电压 （配置量）";
CM_ SG_ 2334584495 M2P_PermitMinVolt_B4_31 "汇流排4最低允许放电电压 （配置量）";
CM_ SG_ 2334584495 M2P_PermitMaxPow_Chg_B4_31 "汇流排4最大允许充电功率";
CM_ SG_ 2334584495 M2P_PermitMaxPow_DisChg_B4_31 "汇流排4最大允许放电功率";
CM_ SG_ 2334650001 M2P_Power_B4_01 "汇流排4实时功率";
CM_ SG_ 2334650001 M2P_SysremEngy_Chg_B4_01 "汇流排4充电剩余能量";
CM_ SG_ 2334650001 M2P_SysremEngy_DisChg_B4_01 "汇流排4放电剩余能量";
CM_ SG_ 2334650001 M2P_SysMaxVolt_B4_01 "汇流排4单体最大电压  ";
CM_ SG_ 2334650002 M2P_Power_B4_02 "汇流排4实时功率";
CM_ SG_ 2334650002 M2P_SysremEngy_Chg_B4_02 "汇流排4充电剩余能量";
CM_ SG_ 2334650002 M2P_SysremEngy_DisChg_B4_02 "汇流排4放电剩余能量";
CM_ SG_ 2334650002 M2P_SysMaxVolt_B4_02 "汇流排4单体最大电压  ";
CM_ SG_ 2334650003 M2P_Power_B4_03 "汇流排4实时功率";
CM_ SG_ 2334650003 M2P_SysremEngy_Chg_B4_03 "汇流排4充电剩余能量";
CM_ SG_ 2334650003 M2P_SysremEngy_DisChg_B4_03 "汇流排4放电剩余能量";
CM_ SG_ 2334650003 M2P_SysMaxVolt_B4_03 "汇流排4单体最大电压  ";
CM_ SG_ 2334650004 M2P_Power_B4_04 "汇流排4实时功率";
CM_ SG_ 2334650004 M2P_SysremEngy_Chg_B4_04 "汇流排4充电剩余能量";
CM_ SG_ 2334650004 M2P_SysremEngy_DisChg_B4_04 "汇流排4放电剩余能量";
CM_ SG_ 2334650004 M2P_SysMaxVolt_B4_04 "汇流排4单体最大电压  ";
CM_ SG_ 2334650005 M2P_Power_B4_05 "汇流排4实时功率";
CM_ SG_ 2334650005 M2P_SysremEngy_Chg_B4_05 "汇流排4充电剩余能量";
CM_ SG_ 2334650005 M2P_SysremEngy_DisChg_B4_05 "汇流排4放电剩余能量";
CM_ SG_ 2334650005 M2P_SysMaxVolt_B4_05 "汇流排4单体最大电压  ";
CM_ SG_ 2334650006 M2P_Power_B4_06 "汇流排4实时功率";
CM_ SG_ 2334650006 M2P_SysremEngy_Chg_B4_06 "汇流排4充电剩余能量";
CM_ SG_ 2334650006 M2P_SysremEngy_DisChg_B4_06 "汇流排4放电剩余能量";
CM_ SG_ 2334650006 M2P_SysMaxVolt_B4_06 "汇流排4单体最大电压  ";
CM_ SG_ 2334650007 M2P_Power_B4_07 "汇流排4实时功率";
CM_ SG_ 2334650007 M2P_SysremEngy_Chg_B4_07 "汇流排4充电剩余能量";
CM_ SG_ 2334650007 M2P_SysremEngy_DisChg_B4_07 "汇流排4放电剩余能量";
CM_ SG_ 2334650007 M2P_SysMaxVolt_B4_07 "汇流排4单体最大电压  ";
CM_ SG_ 2334650008 M2P_Power_B4_08 "汇流排4实时功率";
CM_ SG_ 2334650008 M2P_SysremEngy_Chg_B4_08 "汇流排4充电剩余能量";
CM_ SG_ 2334650008 M2P_SysremEngy_DisChg_B4_08 "汇流排4放电剩余能量";
CM_ SG_ 2334650008 M2P_SysMaxVolt_B4_08 "汇流排4单体最大电压  ";
CM_ SG_ 2334650009 M2P_Power_B4_09 "汇流排4实时功率";
CM_ SG_ 2334650009 M2P_SysremEngy_Chg_B4_09 "汇流排4充电剩余能量";
CM_ SG_ 2334650009 M2P_SysremEngy_DisChg_B4_09 "汇流排4放电剩余能量";
CM_ SG_ 2334650009 M2P_SysMaxVolt_B4_09 "汇流排4单体最大电压  ";
CM_ SG_ 2334650010 M2P_Power_B4_10 "汇流排4实时功率";
CM_ SG_ 2334650010 M2P_SysremEngy_Chg_B4_10 "汇流排4充电剩余能量";
CM_ SG_ 2334650010 M2P_SysremEngy_DisChg_B4_10 "汇流排4放电剩余能量";
CM_ SG_ 2334650010 M2P_SysMaxVolt_B4_10 "汇流排4单体最大电压  ";
CM_ SG_ 2334650011 M2P_Power_B4_11 "汇流排4实时功率";
CM_ SG_ 2334650011 M2P_SysremEngy_Chg_B4_11 "汇流排4充电剩余能量";
CM_ SG_ 2334650011 M2P_SysremEngy_DisChg_B4_11 "汇流排4放电剩余能量";
CM_ SG_ 2334650011 M2P_SysMaxVolt_B4_11 "汇流排4单体最大电压  ";
CM_ SG_ 2334650012 M2P_Power_B4_12 "汇流排4实时功率";
CM_ SG_ 2334650012 M2P_SysremEngy_Chg_B4_12 "汇流排4充电剩余能量";
CM_ SG_ 2334650012 M2P_SysremEngy_DisChg_B4_12 "汇流排4放电剩余能量";
CM_ SG_ 2334650012 M2P_SysMaxVolt_B4_12 "汇流排4单体最大电压  ";
CM_ SG_ 2334650013 M2P_Power_B4_13 "汇流排4实时功率";
CM_ SG_ 2334650013 M2P_SysremEngy_Chg_B4_13 "汇流排4充电剩余能量";
CM_ SG_ 2334650013 M2P_SysremEngy_DisChg_B4_13 "汇流排4放电剩余能量";
CM_ SG_ 2334650013 M2P_SysMaxVolt_B4_13 "汇流排4单体最大电压  ";
CM_ SG_ 2334650014 M2P_Power_B4_14 "汇流排4实时功率";
CM_ SG_ 2334650014 M2P_SysremEngy_Chg_B4_14 "汇流排4充电剩余能量";
CM_ SG_ 2334650014 M2P_SysremEngy_DisChg_B4_14 "汇流排4放电剩余能量";
CM_ SG_ 2334650014 M2P_SysMaxVolt_B4_14 "汇流排4单体最大电压  ";
CM_ SG_ 2334650015 M2P_Power_B4_15 "汇流排4实时功率";
CM_ SG_ 2334650015 M2P_SysremEngy_Chg_B4_15 "汇流排4充电剩余能量";
CM_ SG_ 2334650015 M2P_SysremEngy_DisChg_B4_15 "汇流排4放电剩余能量";
CM_ SG_ 2334650015 M2P_SysMaxVolt_B4_15 "汇流排4单体最大电压  ";
CM_ SG_ 2334650016 M2P_Power_B4_16 "汇流排4实时功率";
CM_ SG_ 2334650016 M2P_SysremEngy_Chg_B4_16 "汇流排4充电剩余能量";
CM_ SG_ 2334650016 M2P_SysremEngy_DisChg_B4_16 "汇流排4放电剩余能量";
CM_ SG_ 2334650016 M2P_SysMaxVolt_B4_16 "汇流排4单体最大电压  ";
CM_ SG_ 2334650017 M2P_Power_B4_17 "汇流排4实时功率";
CM_ SG_ 2334650017 M2P_SysremEngy_Chg_B4_17 "汇流排4充电剩余能量";
CM_ SG_ 2334650017 M2P_SysremEngy_DisChg_B4_17 "汇流排4放电剩余能量";
CM_ SG_ 2334650017 M2P_SysMaxVolt_B4_17 "汇流排4单体最大电压  ";
CM_ SG_ 2334650018 M2P_Power_B4_18 "汇流排4实时功率";
CM_ SG_ 2334650018 M2P_SysremEngy_Chg_B4_18 "汇流排4充电剩余能量";
CM_ SG_ 2334650018 M2P_SysremEngy_DisChg_B4_18 "汇流排4放电剩余能量";
CM_ SG_ 2334650018 M2P_SysMaxVolt_B4_18 "汇流排4单体最大电压  ";
CM_ SG_ 2334650019 M2P_Power_B4_19 "汇流排4实时功率";
CM_ SG_ 2334650019 M2P_SysremEngy_Chg_B4_19 "汇流排4充电剩余能量";
CM_ SG_ 2334650019 M2P_SysremEngy_DisChg_B4_19 "汇流排4放电剩余能量";
CM_ SG_ 2334650019 M2P_SysMaxVolt_B4_19 "汇流排4单体最大电压  ";
CM_ SG_ 2334650020 M2P_Power_B4_20 "汇流排4实时功率";
CM_ SG_ 2334650020 M2P_SysremEngy_Chg_B4_20 "汇流排4充电剩余能量";
CM_ SG_ 2334650020 M2P_SysremEngy_DisChg_B4_20 "汇流排4放电剩余能量";
CM_ SG_ 2334650020 M2P_SysMaxVolt_B4_20 "汇流排4单体最大电压  ";
CM_ SG_ 2334650021 M2P_Power_B4_21 "汇流排4实时功率";
CM_ SG_ 2334650021 M2P_SysremEngy_Chg_B4_21 "汇流排4充电剩余能量";
CM_ SG_ 2334650021 M2P_SysremEngy_DisChg_B4_21 "汇流排4放电剩余能量";
CM_ SG_ 2334650021 M2P_SysMaxVolt_B4_21 "汇流排4单体最大电压  ";
CM_ SG_ 2334650022 M2P_Power_B4_22 "汇流排4实时功率";
CM_ SG_ 2334650022 M2P_SysremEngy_Chg_B4_22 "汇流排4充电剩余能量";
CM_ SG_ 2334650022 M2P_SysremEngy_DisChg_B4_22 "汇流排4放电剩余能量";
CM_ SG_ 2334650022 M2P_SysMaxVolt_B4_22 "汇流排4单体最大电压  ";
CM_ SG_ 2334650023 M2P_Power_B4_23 "汇流排4实时功率";
CM_ SG_ 2334650023 M2P_SysremEngy_Chg_B4_23 "汇流排4充电剩余能量";
CM_ SG_ 2334650023 M2P_SysremEngy_DisChg_B4_23 "汇流排4放电剩余能量";
CM_ SG_ 2334650023 M2P_SysMaxVolt_B4_23 "汇流排4单体最大电压  ";
CM_ SG_ 2334650024 M2P_Power_B4_24 "汇流排4实时功率";
CM_ SG_ 2334650024 M2P_SysremEngy_Chg_B4_24 "汇流排4充电剩余能量";
CM_ SG_ 2334650024 M2P_SysremEngy_DisChg_B4_24 "汇流排4放电剩余能量";
CM_ SG_ 2334650024 M2P_SysMaxVolt_B4_24 "汇流排4单体最大电压  ";
CM_ SG_ 2334650025 M2P_Power_B4_25 "汇流排4实时功率";
CM_ SG_ 2334650025 M2P_SysremEngy_Chg_B4_25 "汇流排4充电剩余能量";
CM_ SG_ 2334650025 M2P_SysremEngy_DisChg_B4_25 "汇流排4放电剩余能量";
CM_ SG_ 2334650025 M2P_SysMaxVolt_B4_25 "汇流排4单体最大电压  ";
CM_ SG_ 2334650026 M2P_Power_B4_26 "汇流排4实时功率";
CM_ SG_ 2334650026 M2P_SysremEngy_Chg_B4_26 "汇流排4充电剩余能量";
CM_ SG_ 2334650026 M2P_SysremEngy_DisChg_B4_26 "汇流排4放电剩余能量";
CM_ SG_ 2334650026 M2P_SysMaxVolt_B4_26 "汇流排4单体最大电压  ";
CM_ SG_ 2334650027 M2P_Power_B4_27 "汇流排4实时功率";
CM_ SG_ 2334650027 M2P_SysremEngy_Chg_B4_27 "汇流排4充电剩余能量";
CM_ SG_ 2334650027 M2P_SysremEngy_DisChg_B4_27 "汇流排4放电剩余能量";
CM_ SG_ 2334650027 M2P_SysMaxVolt_B4_27 "汇流排4单体最大电压  ";
CM_ SG_ 2334650028 M2P_Power_B4_28 "汇流排4实时功率";
CM_ SG_ 2334650028 M2P_SysremEngy_Chg_B4_28 "汇流排4充电剩余能量";
CM_ SG_ 2334650028 M2P_SysremEngy_DisChg_B4_28 "汇流排4放电剩余能量";
CM_ SG_ 2334650028 M2P_SysMaxVolt_B4_28 "汇流排4单体最大电压  ";
CM_ SG_ 2334650029 M2P_Power_B4_29 "汇流排4实时功率";
CM_ SG_ 2334650029 M2P_SysremEngy_Chg_B4_29 "汇流排4充电剩余能量";
CM_ SG_ 2334650029 M2P_SysremEngy_DisChg_B4_29 "汇流排4放电剩余能量";
CM_ SG_ 2334650029 M2P_SysMaxVolt_B4_29 "汇流排4单体最大电压  ";
CM_ SG_ 2334650030 M2P_Power_B4_30 "汇流排4实时功率";
CM_ SG_ 2334650030 M2P_SysremEngy_Chg_B4_30 "汇流排4充电剩余能量";
CM_ SG_ 2334650030 M2P_SysremEngy_DisChg_B4_30 "汇流排4放电剩余能量";
CM_ SG_ 2334650030 M2P_SysMaxVolt_B4_30 "汇流排4单体最大电压  ";
CM_ SG_ 2334650031 M2P_Power_B4_31 "汇流排4实时功率";
CM_ SG_ 2334650031 M2P_SysremEngy_Chg_B4_31 "汇流排4充电剩余能量";
CM_ SG_ 2334650031 M2P_SysremEngy_DisChg_B4_31 "汇流排4放电剩余能量";
CM_ SG_ 2334650031 M2P_SysMaxVolt_B4_31 "汇流排4单体最大电压  ";
CM_ SG_ 2334715537 M2P_SysMinVolt_B4_01 "汇流排4单体最小电压";
CM_ SG_ 2334715537 M2P_SysAvgVolt_B4_01 "汇流排4单体平均电压";
CM_ SG_ 2334715537 M2P_BMS_Status_B4 "汇流排4能量状态";
CM_ SG_ 2334715537 M2P_SOC_B4 "汇流排4系统SOC";
CM_ SG_ 2334715537 M2P_SOH_B4 "汇流排4系统SOH";
CM_ SG_ 2334715537 Reserved_01 "预留";
CM_ SG_ 2334715538 M2P_SysMinVolt_B4_02 "汇流排4单体最小电压";
CM_ SG_ 2334715538 M2P_SysAvgVolt_B4_02 "汇流排4单体平均电压";
CM_ SG_ 2334715538 M2P_BMS_Status_B4 "汇流排4能量状态";
CM_ SG_ 2334715538 M2P_SOC_B4 "汇流排4系统SOC";
CM_ SG_ 2334715538 M2P_SOH_B4 "汇流排4系统SOH";
CM_ SG_ 2334715538 Reserved_02 "预留";
CM_ SG_ 2334715539 M2P_SysMinVolt_B4_03 "汇流排4单体最小电压";
CM_ SG_ 2334715539 M2P_SysAvgVolt_B4_03 "汇流排4单体平均电压";
CM_ SG_ 2334715539 M2P_BMS_Status_B4 "汇流排4能量状态";
CM_ SG_ 2334715539 M2P_SOC_B4 "汇流排4系统SOC";
CM_ SG_ 2334715539 M2P_SOH_B4 "汇流排4系统SOH";
CM_ SG_ 2334715539 Reserved_03 "预留";
CM_ SG_ 2334715540 M2P_SysMinVolt_B4_04 "汇流排4单体最小电压";
CM_ SG_ 2334715540 M2P_SysAvgVolt_B4_04 "汇流排4单体平均电压";
CM_ SG_ 2334715540 M2P_BMS_Status_B4 "汇流排4能量状态";
CM_ SG_ 2334715540 M2P_SOC_B4 "汇流排4系统SOC";
CM_ SG_ 2334715540 M2P_SOH_B4 "汇流排4系统SOH";
CM_ SG_ 2334715540 Reserved_04 "预留";
CM_ SG_ 2334715541 M2P_SysMinVolt_B4_05 "汇流排4单体最小电压";
CM_ SG_ 2334715541 M2P_SysAvgVolt_B4_05 "汇流排4单体平均电压";
CM_ SG_ 2334715541 M2P_BMS_Status_B4 "汇流排4能量状态";
CM_ SG_ 2334715541 M2P_SOC_B4 "汇流排4系统SOC";
CM_ SG_ 2334715541 M2P_SOH_B4 "汇流排4系统SOH";
CM_ SG_ 2334715541 Reserved_05 "预留";
CM_ SG_ 2334715542 M2P_SysMinVolt_B4_06 "汇流排4单体最小电压";
CM_ SG_ 2334715542 M2P_SysAvgVolt_B4_06 "汇流排4单体平均电压";
CM_ SG_ 2334715542 M2P_BMS_Status_B4 "汇流排4能量状态";
CM_ SG_ 2334715542 M2P_SOC_B4 "汇流排4系统SOC";
CM_ SG_ 2334715542 M2P_SOH_B4 "汇流排4系统SOH";
CM_ SG_ 2334715542 Reserved_06 "预留";
CM_ SG_ 2334715543 M2P_SysMinVolt_B4_07 "汇流排4单体最小电压";
CM_ SG_ 2334715543 M2P_SysAvgVolt_B4_07 "汇流排4单体平均电压";
CM_ SG_ 2334715543 M2P_BMS_Status_B4 "汇流排4能量状态";
CM_ SG_ 2334715543 M2P_SOC_B4 "汇流排4系统SOC";
CM_ SG_ 2334715543 M2P_SOH_B4 "汇流排4系统SOH";
CM_ SG_ 2334715543 Reserved_07 "预留";
CM_ SG_ 2334715544 M2P_SysMinVolt_B4_08 "汇流排4单体最小电压";
CM_ SG_ 2334715544 M2P_SysAvgVolt_B4_08 "汇流排4单体平均电压";
CM_ SG_ 2334715544 M2P_BMS_Status_B4 "汇流排4能量状态";
CM_ SG_ 2334715544 M2P_SOC_B4 "汇流排4系统SOC";
CM_ SG_ 2334715544 M2P_SOH_B4 "汇流排4系统SOH";
CM_ SG_ 2334715544 Reserved_08 "预留";
CM_ SG_ 2334715545 M2P_SysMinVolt_B4_09 "汇流排4单体最小电压";
CM_ SG_ 2334715545 M2P_SysAvgVolt_B4_09 "汇流排4单体平均电压";
CM_ SG_ 2334715545 M2P_BMS_Status_B4 "汇流排4能量状态";
CM_ SG_ 2334715545 M2P_SOC_B4 "汇流排4系统SOC";
CM_ SG_ 2334715545 M2P_SOH_B4 "汇流排4系统SOH";
CM_ SG_ 2334715545 Reserved_09 "预留";
CM_ SG_ 2334715546 M2P_SysMinVolt_B4_10 "汇流排4单体最小电压";
CM_ SG_ 2334715546 M2P_SysAvgVolt_B4_10 "汇流排4单体平均电压";
CM_ SG_ 2334715546 M2P_BMS_Status_B4 "汇流排4能量状态";
CM_ SG_ 2334715546 M2P_SOC_B4 "汇流排4系统SOC";
CM_ SG_ 2334715546 M2P_SOH_B4 "汇流排4系统SOH";
CM_ SG_ 2334715546 Reserved_10 "预留";
CM_ SG_ 2334715547 M2P_SysMinVolt_B4_11 "汇流排4单体最小电压";
CM_ SG_ 2334715547 M2P_SysAvgVolt_B4_11 "汇流排4单体平均电压";
CM_ SG_ 2334715547 M2P_BMS_Status_B4 "汇流排4能量状态";
CM_ SG_ 2334715547 M2P_SOC_B4 "汇流排4系统SOC";
CM_ SG_ 2334715547 M2P_SOH_B4 "汇流排4系统SOH";
CM_ SG_ 2334715547 Reserved_11 "预留";
CM_ SG_ 2334715548 M2P_SysMinVolt_B4_12 "汇流排4单体最小电压";
CM_ SG_ 2334715548 M2P_SysAvgVolt_B4_12 "汇流排4单体平均电压";
CM_ SG_ 2334715548 M2P_BMS_Status_B4 "汇流排4能量状态";
CM_ SG_ 2334715548 M2P_SOC_B4 "汇流排4系统SOC";
CM_ SG_ 2334715548 M2P_SOH_B4 "汇流排4系统SOH";
CM_ SG_ 2334715548 Reserved_12 "预留";
CM_ SG_ 2334715549 M2P_SysMinVolt_B4_13 "汇流排4单体最小电压";
CM_ SG_ 2334715549 M2P_SysAvgVolt_B4_13 "汇流排4单体平均电压";
CM_ SG_ 2334715549 M2P_BMS_Status_B4 "汇流排4能量状态";
CM_ SG_ 2334715549 M2P_SOC_B4 "汇流排4系统SOC";
CM_ SG_ 2334715549 M2P_SOH_B4 "汇流排4系统SOH";
CM_ SG_ 2334715549 Reserved_13 "预留";
CM_ SG_ 2334715550 M2P_SysMinVolt_B4_14 "汇流排4单体最小电压";
CM_ SG_ 2334715550 M2P_SysAvgVolt_B4_14 "汇流排4单体平均电压";
CM_ SG_ 2334715550 M2P_BMS_Status_B4 "汇流排4能量状态";
CM_ SG_ 2334715550 M2P_SOC_B4 "汇流排4系统SOC";
CM_ SG_ 2334715550 M2P_SOH_B4 "汇流排4系统SOH";
CM_ SG_ 2334715550 Reserved_14 "预留";
CM_ SG_ 2334715551 M2P_SysMinVolt_B4_15 "汇流排4单体最小电压";
CM_ SG_ 2334715551 M2P_SysAvgVolt_B4_15 "汇流排4单体平均电压";
CM_ SG_ 2334715551 M2P_BMS_Status_B4 "汇流排4能量状态";
CM_ SG_ 2334715551 M2P_SOC_B4 "汇流排4系统SOC";
CM_ SG_ 2334715551 M2P_SOH_B4 "汇流排4系统SOH";
CM_ SG_ 2334715551 Reserved_15 "预留";
CM_ SG_ 2334715552 M2P_SysMinVolt_B4_16 "汇流排4单体最小电压";
CM_ SG_ 2334715552 M2P_SysAvgVolt_B4_16 "汇流排4单体平均电压";
CM_ SG_ 2334715552 M2P_BMS_Status_B4 "汇流排4能量状态";
CM_ SG_ 2334715552 M2P_SOC_B4 "汇流排4系统SOC";
CM_ SG_ 2334715552 M2P_SOH_B4 "汇流排4系统SOH";
CM_ SG_ 2334715552 Reserved_16 "预留";
CM_ SG_ 2334715553 M2P_SysMinVolt_B4_17 "汇流排4单体最小电压";
CM_ SG_ 2334715553 M2P_SysAvgVolt_B4_17 "汇流排4单体平均电压";
CM_ SG_ 2334715553 M2P_BMS_Status_B4 "汇流排4能量状态";
CM_ SG_ 2334715553 M2P_SOC_B4 "汇流排4系统SOC";
CM_ SG_ 2334715553 M2P_SOH_B4 "汇流排4系统SOH";
CM_ SG_ 2334715553 Reserved_17 "预留";
CM_ SG_ 2334715554 M2P_SysMinVolt_B4_18 "汇流排4单体最小电压";
CM_ SG_ 2334715554 M2P_SysAvgVolt_B4_18 "汇流排4单体平均电压";
CM_ SG_ 2334715554 M2P_BMS_Status_B4 "汇流排4能量状态";
CM_ SG_ 2334715554 M2P_SOC_B4 "汇流排4系统SOC";
CM_ SG_ 2334715554 M2P_SOH_B4 "汇流排4系统SOH";
CM_ SG_ 2334715554 Reserved_18 "预留";
CM_ SG_ 2334715555 M2P_SysMinVolt_B4_19 "汇流排4单体最小电压";
CM_ SG_ 2334715555 M2P_SysAvgVolt_B4_19 "汇流排4单体平均电压";
CM_ SG_ 2334715555 M2P_BMS_Status_B4 "汇流排4能量状态";
CM_ SG_ 2334715555 M2P_SOC_B4 "汇流排4系统SOC";
CM_ SG_ 2334715555 M2P_SOH_B4 "汇流排4系统SOH";
CM_ SG_ 2334715555 Reserved_19 "预留";
CM_ SG_ 2334715556 M2P_SysMinVolt_B4_20 "汇流排4单体最小电压";
CM_ SG_ 2334715556 M2P_SysAvgVolt_B4_20 "汇流排4单体平均电压";
CM_ SG_ 2334715556 M2P_BMS_Status_B4 "汇流排4能量状态";
CM_ SG_ 2334715556 M2P_SOC_B4 "汇流排4系统SOC";
CM_ SG_ 2334715556 M2P_SOH_B4 "汇流排4系统SOH";
CM_ SG_ 2334715556 Reserved_20 "预留";
VAL_ 2334191249 M2P_Measure_Vol_B3_01 65535 "Invalid" ;
VAL_ 2334191249 M2P_Current_B3_01 65535 "Invalid" ;
VAL_ 2334191249 M2P_PermitMaxCharge_I_B3_01 65535 "Invalid" ;
VAL_ 2334191249 M2P_PermitMaxDisCharge_I_B3_01 65535 "Invalid" ;
VAL_ 2334191250 M2P_Measure_Vol_B3_02 65535 "Invalid" ;
VAL_ 2334191250 M2P_Current_B3_02 65535 "Invalid" ;
VAL_ 2334191250 M2P_PermitMaxCharge_I_B3_02 65535 "Invalid" ;
VAL_ 2334191250 M2P_PermitMaxDisCharge_I_B3_02 65535 "Invalid" ;
VAL_ 2334191251 M2P_Measure_Vol_B3_03 65535 "Invalid" ;
VAL_ 2334191251 M2P_Current_B3_03 65535 "Invalid" ;
VAL_ 2334191251 M2P_PermitMaxCharge_I_B3_03 65535 "Invalid" ;
VAL_ 2334191251 M2P_PermitMaxDisCharge_I_B3_03 65535 "Invalid" ;
VAL_ 2334191252 M2P_Measure_Vol_B3_04 65535 "Invalid" ;
VAL_ 2334191252 M2P_Current_B3_04 65535 "Invalid" ;
VAL_ 2334191252 M2P_PermitMaxCharge_I_B3_04 65535 "Invalid" ;
VAL_ 2334191252 M2P_PermitMaxDisCharge_I_B3_04 65535 "Invalid" ;
VAL_ 2334191253 M2P_Measure_Vol_B3_05 65535 "Invalid" ;
VAL_ 2334191253 M2P_Current_B3_05 65535 "Invalid" ;
VAL_ 2334191253 M2P_PermitMaxCharge_I_B3_05 65535 "Invalid" ;
VAL_ 2334191253 M2P_PermitMaxDisCharge_I_B3_05 65535 "Invalid" ;
VAL_ 2334191254 M2P_Measure_Vol_B3_06 65535 "Invalid" ;
VAL_ 2334191254 M2P_Current_B3_06 65535 "Invalid" ;
VAL_ 2334191254 M2P_PermitMaxCharge_I_B3_06 65535 "Invalid" ;
VAL_ 2334191254 M2P_PermitMaxDisCharge_I_B3_06 65535 "Invalid" ;
VAL_ 2334191255 M2P_Measure_Vol_B3_07 65535 "Invalid" ;
VAL_ 2334191255 M2P_Current_B3_07 65535 "Invalid" ;
VAL_ 2334191255 M2P_PermitMaxCharge_I_B3_07 65535 "Invalid" ;
VAL_ 2334191255 M2P_PermitMaxDisCharge_I_B3_07 65535 "Invalid" ;
VAL_ 2334191256 M2P_Measure_Vol_B3_08 65535 "Invalid" ;
VAL_ 2334191256 M2P_Current_B3_08 65535 "Invalid" ;
VAL_ 2334191256 M2P_PermitMaxCharge_I_B3_08 65535 "Invalid" ;
VAL_ 2334191256 M2P_PermitMaxDisCharge_I_B3_08 65535 "Invalid" ;
VAL_ 2334191257 M2P_Measure_Vol_B3_09 65535 "Invalid" ;
VAL_ 2334191257 M2P_Current_B3_09 65535 "Invalid" ;
VAL_ 2334191257 M2P_PermitMaxCharge_I_B3_09 65535 "Invalid" ;
VAL_ 2334191257 M2P_PermitMaxDisCharge_I_B3_09 65535 "Invalid" ;
VAL_ 2334191258 M2P_Measure_Vol_B3_10 65535 "Invalid" ;
VAL_ 2334191258 M2P_Current_B3_10 65535 "Invalid" ;
VAL_ 2334191258 M2P_PermitMaxCharge_I_B3_10 65535 "Invalid" ;
VAL_ 2334191258 M2P_PermitMaxDisCharge_I_B3_10 65535 "Invalid" ;
VAL_ 2334191259 M2P_Measure_Vol_B3_11 65535 "Invalid" ;
VAL_ 2334191259 M2P_Current_B3_11 65535 "Invalid" ;
VAL_ 2334191259 M2P_PermitMaxCharge_I_B3_11 65535 "Invalid" ;
VAL_ 2334191259 M2P_PermitMaxDisCharge_I_B3_11 65535 "Invalid" ;
VAL_ 2334191260 M2P_Measure_Vol_B3_12 65535 "Invalid" ;
VAL_ 2334191260 M2P_Current_B3_12 65535 "Invalid" ;
VAL_ 2334191260 M2P_PermitMaxCharge_I_B3_12 65535 "Invalid" ;
VAL_ 2334191260 M2P_PermitMaxDisCharge_I_B3_12 65535 "Invalid" ;
VAL_ 2334191261 M2P_Measure_Vol_B3_13 65535 "Invalid" ;
VAL_ 2334191261 M2P_Current_B3_13 65535 "Invalid" ;
VAL_ 2334191261 M2P_PermitMaxCharge_I_B3_13 65535 "Invalid" ;
VAL_ 2334191261 M2P_PermitMaxDisCharge_I_B3_13 65535 "Invalid" ;
VAL_ 2334191262 M2P_Measure_Vol_B3_14 65535 "Invalid" ;
VAL_ 2334191262 M2P_Current_B3_14 65535 "Invalid" ;
VAL_ 2334191262 M2P_PermitMaxCharge_I_B3_14 65535 "Invalid" ;
VAL_ 2334191262 M2P_PermitMaxDisCharge_I_B3_14 65535 "Invalid" ;
VAL_ 2334191263 M2P_Measure_Vol_B3_15 65535 "Invalid" ;
VAL_ 2334191263 M2P_Current_B3_15 65535 "Invalid" ;
VAL_ 2334191263 M2P_PermitMaxCharge_I_B3_15 65535 "Invalid" ;
VAL_ 2334191263 M2P_PermitMaxDisCharge_I_B3_15 65535 "Invalid" ;
VAL_ 2334191264 M2P_Measure_Vol_B3_16 65535 "Invalid" ;
VAL_ 2334191264 M2P_Current_B3_16 65535 "Invalid" ;
VAL_ 2334191264 M2P_PermitMaxCharge_I_B3_16 65535 "Invalid" ;
VAL_ 2334191264 M2P_PermitMaxDisCharge_I_B3_16 65535 "Invalid" ;
VAL_ 2334191265 M2P_Measure_Vol_B3_17 65535 "Invalid" ;
VAL_ 2334191265 M2P_Current_B3_17 65535 "Invalid" ;
VAL_ 2334191265 M2P_PermitMaxCharge_I_B3_17 65535 "Invalid" ;
VAL_ 2334191265 M2P_PermitMaxDisCharge_I_B3_17 65535 "Invalid" ;
VAL_ 2334191266 M2P_Measure_Vol_B3_18 65535 "Invalid" ;
VAL_ 2334191266 M2P_Current_B3_18 65535 "Invalid" ;
VAL_ 2334191266 M2P_PermitMaxCharge_I_B3_18 65535 "Invalid" ;
VAL_ 2334191266 M2P_PermitMaxDisCharge_I_B3_18 65535 "Invalid" ;
VAL_ 2334191267 M2P_Measure_Vol_B3_19 65535 "Invalid" ;
VAL_ 2334191267 M2P_Current_B3_19 65535 "Invalid" ;
VAL_ 2334191267 M2P_PermitMaxCharge_I_B3_19 65535 "Invalid" ;
VAL_ 2334191267 M2P_PermitMaxDisCharge_I_B3_19 65535 "Invalid" ;
VAL_ 2334191268 M2P_Measure_Vol_B3_20 65535 "Invalid" ;
VAL_ 2334191268 M2P_Current_B3_20 65535 "Invalid" ;
VAL_ 2334191268 M2P_PermitMaxCharge_I_B3_20 65535 "Invalid" ;
VAL_ 2334191268 M2P_PermitMaxDisCharge_I_B3_20 65535 "Invalid" ;
VAL_ 2334191269 M2P_Measure_Vol_B3_21 65535 "Invalid" ;
VAL_ 2334191269 M2P_Current_B3_21 65535 "Invalid" ;
VAL_ 2334191269 M2P_PermitMaxCharge_I_B3_21 65535 "Invalid" ;
VAL_ 2334191269 M2P_PermitMaxDisCharge_I_B3_21 65535 "Invalid" ;
VAL_ 2334191270 M2P_Measure_Vol_B3_22 65535 "Invalid" ;
VAL_ 2334191270 M2P_Current_B3_22 65535 "Invalid" ;
VAL_ 2334191270 M2P_PermitMaxCharge_I_B3_22 65535 "Invalid" ;
VAL_ 2334191270 M2P_PermitMaxDisCharge_I_B3_22 65535 "Invalid" ;
VAL_ 2334191271 M2P_Measure_Vol_B3_23 65535 "Invalid" ;
VAL_ 2334191271 M2P_Current_B3_23 65535 "Invalid" ;
VAL_ 2334191271 M2P_PermitMaxCharge_I_B3_23 65535 "Invalid" ;
VAL_ 2334191271 M2P_PermitMaxDisCharge_I_B3_23 65535 "Invalid" ;
VAL_ 2334191272 M2P_Measure_Vol_B3_24 65535 "Invalid" ;
VAL_ 2334191272 M2P_Current_B3_24 65535 "Invalid" ;
VAL_ 2334191272 M2P_PermitMaxCharge_I_B3_24 65535 "Invalid" ;
VAL_ 2334191272 M2P_PermitMaxDisCharge_I_B3_24 65535 "Invalid" ;
VAL_ 2334191273 M2P_Measure_Vol_B3_25 65535 "Invalid" ;
VAL_ 2334191273 M2P_Current_B3_25 65535 "Invalid" ;
VAL_ 2334191273 M2P_PermitMaxCharge_I_B3_25 65535 "Invalid" ;
VAL_ 2334191273 M2P_PermitMaxDisCharge_I_B3_25 65535 "Invalid" ;
VAL_ 2334191274 M2P_Measure_Vol_B3_26 65535 "Invalid" ;
VAL_ 2334191274 M2P_Current_B3_26 65535 "Invalid" ;
VAL_ 2334191274 M2P_PermitMaxCharge_I_B3_26 65535 "Invalid" ;
VAL_ 2334191274 M2P_PermitMaxDisCharge_I_B3_26 65535 "Invalid" ;
VAL_ 2334191275 M2P_Measure_Vol_B3_27 65535 "Invalid" ;
VAL_ 2334191275 M2P_Current_B3_27 65535 "Invalid" ;
VAL_ 2334191275 M2P_PermitMaxCharge_I_B3_27 65535 "Invalid" ;
VAL_ 2334191275 M2P_PermitMaxDisCharge_I_B3_27 65535 "Invalid" ;
VAL_ 2334191276 M2P_Measure_Vol_B3_28 65535 "Invalid" ;
VAL_ 2334191276 M2P_Current_B3_28 65535 "Invalid" ;
VAL_ 2334191276 M2P_PermitMaxCharge_I_B3_28 65535 "Invalid" ;
VAL_ 2334191276 M2P_PermitMaxDisCharge_I_B3_28 65535 "Invalid" ;
VAL_ 2334191277 M2P_Measure_Vol_B3_29 65535 "Invalid" ;
VAL_ 2334191277 M2P_Current_B3_29 65535 "Invalid" ;
VAL_ 2334191277 M2P_PermitMaxCharge_I_B3_29 65535 "Invalid" ;
VAL_ 2334191277 M2P_PermitMaxDisCharge_I_B3_29 65535 "Invalid" ;
VAL_ 2334191278 M2P_Measure_Vol_B3_30 65535 "Invalid" ;
VAL_ 2334191278 M2P_Current_B3_30 65535 "Invalid" ;
VAL_ 2334191278 M2P_PermitMaxCharge_I_B3_30 65535 "Invalid" ;
VAL_ 2334191278 M2P_PermitMaxDisCharge_I_B3_30 65535 "Invalid" ;
VAL_ 2334191279 M2P_Measure_Vol_B3_31 65535 "Invalid" ;
VAL_ 2334191279 M2P_Current_B3_31 65535 "Invalid" ;
VAL_ 2334191279 M2P_PermitMaxCharge_I_B3_31 65535 "Invalid" ;
VAL_ 2334191279 M2P_PermitMaxDisCharge_I_B3_31 65535 "Invalid" ;
VAL_ 2334322321 M2P_SysremEngy_Chg_B3_01 65535 "Invalid" ;
VAL_ 2334322321 M2P_SysremEngy_DisChg_B3_01 65535 "Invalid" ;
VAL_ 2334322322 M2P_SysremEngy_Chg_B3_02 65535 "Invalid" ;
VAL_ 2334322322 M2P_SysremEngy_DisChg_B3_02 65535 "Invalid" ;
VAL_ 2334322323 M2P_SysremEngy_Chg_B3_03 65535 "Invalid" ;
VAL_ 2334322323 M2P_SysremEngy_DisChg_B3_03 65535 "Invalid" ;
VAL_ 2334322324 M2P_SysremEngy_Chg_B3_04 65535 "Invalid" ;
VAL_ 2334322324 M2P_SysremEngy_DisChg_B3_04 65535 "Invalid" ;
VAL_ 2334322325 M2P_SysremEngy_Chg_B3_05 65535 "Invalid" ;
VAL_ 2334322325 M2P_SysremEngy_DisChg_B3_05 65535 "Invalid" ;
VAL_ 2334322326 M2P_SysremEngy_Chg_B3_06 65535 "Invalid" ;
VAL_ 2334322326 M2P_SysremEngy_DisChg_B3_06 65535 "Invalid" ;
VAL_ 2334322327 M2P_SysremEngy_Chg_B3_07 65535 "Invalid" ;
VAL_ 2334322327 M2P_SysremEngy_DisChg_B3_07 65535 "Invalid" ;
VAL_ 2334322328 M2P_SysremEngy_Chg_B3_08 65535 "Invalid" ;
VAL_ 2334322328 M2P_SysremEngy_DisChg_B3_08 65535 "Invalid" ;
VAL_ 2334322329 M2P_SysremEngy_Chg_B3_09 65535 "Invalid" ;
VAL_ 2334322329 M2P_SysremEngy_DisChg_B3_09 65535 "Invalid" ;
VAL_ 2334322330 M2P_SysremEngy_Chg_B3_10 65535 "Invalid" ;
VAL_ 2334322330 M2P_SysremEngy_DisChg_B3_10 65535 "Invalid" ;
VAL_ 2334322331 M2P_SysremEngy_Chg_B3_11 65535 "Invalid" ;
VAL_ 2334322331 M2P_SysremEngy_DisChg_B3_11 65535 "Invalid" ;
VAL_ 2334322332 M2P_SysremEngy_Chg_B3_12 65535 "Invalid" ;
VAL_ 2334322332 M2P_SysremEngy_DisChg_B3_12 65535 "Invalid" ;
VAL_ 2334322333 M2P_SysremEngy_Chg_B3_13 65535 "Invalid" ;
VAL_ 2334322333 M2P_SysremEngy_DisChg_B3_13 65535 "Invalid" ;
VAL_ 2334322334 M2P_SysremEngy_Chg_B3_14 65535 "Invalid" ;
VAL_ 2334322334 M2P_SysremEngy_DisChg_B3_14 65535 "Invalid" ;
VAL_ 2334322335 M2P_SysremEngy_Chg_B3_15 65535 "Invalid" ;
VAL_ 2334322335 M2P_SysremEngy_DisChg_B3_15 65535 "Invalid" ;
VAL_ 2334322336 M2P_SysremEngy_Chg_B3_16 65535 "Invalid" ;
VAL_ 2334322336 M2P_SysremEngy_DisChg_B3_16 65535 "Invalid" ;
VAL_ 2334322337 M2P_SysremEngy_Chg_B3_17 65535 "Invalid" ;
VAL_ 2334322337 M2P_SysremEngy_DisChg_B3_17 65535 "Invalid" ;
VAL_ 2334322338 M2P_SysremEngy_Chg_B3_18 65535 "Invalid" ;
VAL_ 2334322338 M2P_SysremEngy_DisChg_B3_18 65535 "Invalid" ;
VAL_ 2334322339 M2P_SysremEngy_Chg_B3_19 65535 "Invalid" ;
VAL_ 2334322339 M2P_SysremEngy_DisChg_B3_19 65535 "Invalid" ;
VAL_ 2334322340 M2P_SysremEngy_Chg_B3_20 65535 "Invalid" ;
VAL_ 2334322340 M2P_SysremEngy_DisChg_B3_20 65535 "Invalid" ;
VAL_ 2334322341 M2P_SysremEngy_Chg_B3_21 65535 "Invalid" ;
VAL_ 2334322341 M2P_SysremEngy_DisChg_B3_21 65535 "Invalid" ;
VAL_ 2334322342 M2P_SysremEngy_Chg_B3_22 65535 "Invalid" ;
VAL_ 2334322342 M2P_SysremEngy_DisChg_B3_22 65535 "Invalid" ;
VAL_ 2334322343 M2P_SysremEngy_Chg_B3_23 65535 "Invalid" ;
VAL_ 2334322343 M2P_SysremEngy_DisChg_B3_23 65535 "Invalid" ;
VAL_ 2334322344 M2P_SysremEngy_Chg_B3_24 65535 "Invalid" ;
VAL_ 2334322344 M2P_SysremEngy_DisChg_B3_24 65535 "Invalid" ;
VAL_ 2334322345 M2P_SysremEngy_Chg_B3_25 65535 "Invalid" ;
VAL_ 2334322345 M2P_SysremEngy_DisChg_B3_25 65535 "Invalid" ;
VAL_ 2334322346 M2P_SysremEngy_Chg_B3_26 65535 "Invalid" ;
VAL_ 2334322346 M2P_SysremEngy_DisChg_B3_26 65535 "Invalid" ;
VAL_ 2334322347 M2P_SysremEngy_Chg_B3_27 65535 "Invalid" ;
VAL_ 2334322347 M2P_SysremEngy_DisChg_B3_27 65535 "Invalid" ;
VAL_ 2334322348 M2P_SysremEngy_Chg_B3_28 65535 "Invalid" ;
VAL_ 2334322348 M2P_SysremEngy_DisChg_B3_28 65535 "Invalid" ;
VAL_ 2334322349 M2P_SysremEngy_Chg_B3_29 65535 "Invalid" ;
VAL_ 2334322349 M2P_SysremEngy_DisChg_B3_29 65535 "Invalid" ;
VAL_ 2334322350 M2P_SysremEngy_Chg_B3_30 65535 "Invalid" ;
VAL_ 2334322350 M2P_SysremEngy_DisChg_B3_30 65535 "Invalid" ;
VAL_ 2334322351 M2P_SysremEngy_Chg_B3_31 65535 "Invalid" ;
VAL_ 2334322351 M2P_SysremEngy_DisChg_B3_31 65535 "Invalid" ;
VAL_ 2334387857 M2P_BMS_Status_B3 0 "初始化状态" 1 "非满充满放状态" 2 "满充状态" 3 "满放状态" ;
VAL_ 2334387857 M2P_SOC_B3 1023 "Null" ;
VAL_ 2334387857 M2P_SOH_B3 255 "Null" ;
VAL_ 2334387858 M2P_BMS_Status_B3 0 "初始化状态" 1 "非满充满放状态" 2 "满充状态" 3 "满放状态" ;
VAL_ 2334387858 M2P_SOC_B3 1023 "Null" ;
VAL_ 2334387858 M2P_SOH_B3 255 "Null" ;
VAL_ 2334387859 M2P_BMS_Status_B3 0 "初始化状态" 1 "非满充满放状态" 2 "满充状态" 3 "满放状态" ;
VAL_ 2334387859 M2P_SOC_B3 1023 "Null" ;
VAL_ 2334387859 M2P_SOH_B3 255 "Null" ;
VAL_ 2334387860 M2P_BMS_Status_B3 0 "初始化状态" 1 "非满充满放状态" 2 "满充状态" 3 "满放状态" ;
VAL_ 2334387860 M2P_SOC_B3 1023 "Null" ;
VAL_ 2334387860 M2P_SOH_B3 255 "Null" ;
VAL_ 2334387861 M2P_BMS_Status_B3 0 "初始化状态" 1 "非满充满放状态" 2 "满充状态" 3 "满放状态" ;
VAL_ 2334387861 M2P_SOC_B3 1023 "Null" ;
VAL_ 2334387861 M2P_SOH_B3 255 "Null" ;
VAL_ 2334387862 M2P_BMS_Status_B3 0 "初始化状态" 1 "非满充满放状态" 2 "满充状态" 3 "满放状态" ;
VAL_ 2334387862 M2P_SOC_B3 1023 "Null" ;
VAL_ 2334387862 M2P_SOH_B3 255 "Null" ;
VAL_ 2334387863 M2P_BMS_Status_B3 0 "初始化状态" 1 "非满充满放状态" 2 "满充状态" 3 "满放状态" ;
VAL_ 2334387863 M2P_SOC_B3 1023 "Null" ;
VAL_ 2334387863 M2P_SOH_B3 255 "Null" ;
VAL_ 2334387864 M2P_BMS_Status_B3 0 "初始化状态" 1 "非满充满放状态" 2 "满充状态" 3 "满放状态" ;
VAL_ 2334387864 M2P_SOC_B3 1023 "Null" ;
VAL_ 2334387864 M2P_SOH_B3 255 "Null" ;
VAL_ 2334387865 M2P_BMS_Status_B3 0 "初始化状态" 1 "非满充满放状态" 2 "满充状态" 3 "满放状态" ;
VAL_ 2334387865 M2P_SOC_B3 1023 "Null" ;
VAL_ 2334387865 M2P_SOH_B3 255 "Null" ;
VAL_ 2334387866 M2P_BMS_Status_B3 0 "初始化状态" 1 "非满充满放状态" 2 "满充状态" 3 "满放状态" ;
VAL_ 2334387866 M2P_SOC_B3 1023 "Null" ;
VAL_ 2334387866 M2P_SOH_B3 255 "Null" ;
VAL_ 2334387867 M2P_BMS_Status_B3 0 "初始化状态" 1 "非满充满放状态" 2 "满充状态" 3 "满放状态" ;
VAL_ 2334387867 M2P_SOC_B3 1023 "Null" ;
VAL_ 2334387867 M2P_SOH_B3 255 "Null" ;
VAL_ 2334387868 M2P_BMS_Status_B3 0 "初始化状态" 1 "非满充满放状态" 2 "满充状态" 3 "满放状态" ;
VAL_ 2334387868 M2P_SOC_B3 1023 "Null" ;
VAL_ 2334387868 M2P_SOH_B3 255 "Null" ;
VAL_ 2334387869 M2P_BMS_Status_B3 0 "初始化状态" 1 "非满充满放状态" 2 "满充状态" 3 "满放状态" ;
VAL_ 2334387869 M2P_SOC_B3 1023 "Null" ;
VAL_ 2334387869 M2P_SOH_B3 255 "Null" ;
VAL_ 2334387870 M2P_BMS_Status_B3 0 "初始化状态" 1 "非满充满放状态" 2 "满充状态" 3 "满放状态" ;
VAL_ 2334387870 M2P_SOC_B3 1023 "Null" ;
VAL_ 2334387870 M2P_SOH_B3 255 "Null" ;
VAL_ 2334387871 M2P_BMS_Status_B3 0 "初始化状态" 1 "非满充满放状态" 2 "满充状态" 3 "满放状态" ;
VAL_ 2334387871 M2P_SOC_B3 1023 "Null" ;
VAL_ 2334387871 M2P_SOH_B3 255 "Null" ;
VAL_ 2334387872 M2P_BMS_Status_B3 0 "初始化状态" 1 "非满充满放状态" 2 "满充状态" 3 "满放状态" ;
VAL_ 2334387872 M2P_SOC_B3 1023 "Null" ;
VAL_ 2334387872 M2P_SOH_B3 255 "Null" ;
VAL_ 2334387873 M2P_BMS_Status_B3 0 "初始化状态" 1 "非满充满放状态" 2 "满充状态" 3 "满放状态" ;
VAL_ 2334387873 M2P_SOC_B3 1023 "Null" ;
VAL_ 2334387873 M2P_SOH_B3 255 "Null" ;
VAL_ 2334387874 M2P_BMS_Status_B3 0 "初始化状态" 1 "非满充满放状态" 2 "满充状态" 3 "满放状态" ;
VAL_ 2334387874 M2P_SOC_B3 1023 "Null" ;
VAL_ 2334387874 M2P_SOH_B3 255 "Null" ;
VAL_ 2334387875 M2P_BMS_Status_B3 0 "初始化状态" 1 "非满充满放状态" 2 "满充状态" 3 "满放状态" ;
VAL_ 2334387875 M2P_SOC_B3 1023 "Null" ;
VAL_ 2334387875 M2P_SOH_B3 255 "Null" ;
VAL_ 2334387876 M2P_BMS_Status_B3 0 "初始化状态" 1 "非满充满放状态" 2 "满充状态" 3 "满放状态" ;
VAL_ 2334387876 M2P_SOC_B3 1023 "Null" ;
VAL_ 2334387876 M2P_SOH_B3 255 "Null" ;
VAL_ 2334387877 M2P_BMS_Status_B3 0 "初始化状态" 1 "非满充满放状态" 2 "满充状态" 3 "满放状态" ;
VAL_ 2334387877 M2P_SOC_B3 1023 "Null" ;
VAL_ 2334387877 M2P_SOH_B3 255 "Null" ;
VAL_ 2334387878 M2P_BMS_Status_B3 0 "初始化状态" 1 "非满充满放状态" 2 "满充状态" 3 "满放状态" ;
VAL_ 2334387878 M2P_SOC_B3 1023 "Null" ;
VAL_ 2334387878 M2P_SOH_B3 255 "Null" ;
VAL_ 2334387879 M2P_BMS_Status_B3 0 "初始化状态" 1 "非满充满放状态" 2 "满充状态" 3 "满放状态" ;
VAL_ 2334387879 M2P_SOC_B3 1023 "Null" ;
VAL_ 2334387879 M2P_SOH_B3 255 "Null" ;
VAL_ 2334387880 M2P_BMS_Status_B3 0 "初始化状态" 1 "非满充满放状态" 2 "满充状态" 3 "满放状态" ;
VAL_ 2334387880 M2P_SOC_B3 1023 "Null" ;
VAL_ 2334387880 M2P_SOH_B3 255 "Null" ;
VAL_ 2334387881 M2P_BMS_Status_B3 0 "初始化状态" 1 "非满充满放状态" 2 "满充状态" 3 "满放状态" ;
VAL_ 2334387881 M2P_SOC_B3 1023 "Null" ;
VAL_ 2334387881 M2P_SOH_B3 255 "Null" ;
VAL_ 2334387882 M2P_BMS_Status_B3 0 "初始化状态" 1 "非满充满放状态" 2 "满充状态" 3 "满放状态" ;
VAL_ 2334387882 M2P_SOC_B3 1023 "Null" ;
VAL_ 2334387882 M2P_SOH_B3 255 "Null" ;
VAL_ 2334387883 M2P_BMS_Status_B3 0 "初始化状态" 1 "非满充满放状态" 2 "满充状态" 3 "满放状态" ;
VAL_ 2334387883 M2P_SOC_B3 1023 "Null" ;
VAL_ 2334387883 M2P_SOH_B3 255 "Null" ;
VAL_ 2334387884 M2P_BMS_Status_B3 0 "初始化状态" 1 "非满充满放状态" 2 "满充状态" 3 "满放状态" ;
VAL_ 2334387884 M2P_SOC_B3 1023 "Null" ;
VAL_ 2334387884 M2P_SOH_B3 255 "Null" ;
VAL_ 2334387885 M2P_BMS_Status_B3 0 "初始化状态" 1 "非满充满放状态" 2 "满充状态" 3 "满放状态" ;
VAL_ 2334387885 M2P_SOC_B3 1023 "Null" ;
VAL_ 2334387885 M2P_SOH_B3 255 "Null" ;
VAL_ 2334387886 M2P_BMS_Status_B3 0 "初始化状态" 1 "非满充满放状态" 2 "满充状态" 3 "满放状态" ;
VAL_ 2334387886 M2P_SOC_B3 1023 "Null" ;
VAL_ 2334387886 M2P_SOH_B3 255 "Null" ;
VAL_ 2334387887 M2P_BMS_Status_B3 0 "初始化状态" 1 "非满充满放状态" 2 "满充状态" 3 "满放状态" ;
VAL_ 2334387887 M2P_SOC_B3 1023 "Null" ;
VAL_ 2334387887 M2P_SOH_B3 255 "Null" ;
VAL_ 2334453393 M2P_SOE_Charge_B3 1023 "Null" ;
VAL_ 2334453393 M2P_SOE_Discharge_B3 1023 "Null" ;
VAL_ 2334453394 M2P_SOE_Charge_B3 1023 "Null" ;
VAL_ 2334453394 M2P_SOE_Discharge_B3 1023 "Null" ;
VAL_ 2334453395 M2P_SOE_Charge_B3 1023 "Null" ;
VAL_ 2334453395 M2P_SOE_Discharge_B3 1023 "Null" ;
VAL_ 2334453396 M2P_SOE_Charge_B3 1023 "Null" ;
VAL_ 2334453396 M2P_SOE_Discharge_B3 1023 "Null" ;
VAL_ 2334453397 M2P_SOE_Charge_B3 1023 "Null" ;
VAL_ 2334453397 M2P_SOE_Discharge_B3 1023 "Null" ;
VAL_ 2334453398 M2P_SOE_Charge_B3 1023 "Null" ;
VAL_ 2334453398 M2P_SOE_Discharge_B3 1023 "Null" ;
VAL_ 2334453399 M2P_SOE_Charge_B3 1023 "Null" ;
VAL_ 2334453399 M2P_SOE_Discharge_B3 1023 "Null" ;
VAL_ 2334453400 M2P_SOE_Charge_B3 1023 "Null" ;
VAL_ 2334453400 M2P_SOE_Discharge_B3 1023 "Null" ;
VAL_ 2334453401 M2P_SOE_Charge_B3 1023 "Null" ;
VAL_ 2334453401 M2P_SOE_Discharge_B3 1023 "Null" ;
VAL_ 2334453402 M2P_SOE_Charge_B3 1023 "Null" ;
VAL_ 2334453402 M2P_SOE_Discharge_B3 1023 "Null" ;
VAL_ 2334453403 M2P_SOE_Charge_B3 1023 "Null" ;
VAL_ 2334453403 M2P_SOE_Discharge_B3 1023 "Null" ;
VAL_ 2334453404 M2P_SOE_Charge_B3 1023 "Null" ;
VAL_ 2334453404 M2P_SOE_Discharge_B3 1023 "Null" ;
VAL_ 2334453405 M2P_SOE_Charge_B3 1023 "Null" ;
VAL_ 2334453405 M2P_SOE_Discharge_B3 1023 "Null" ;
VAL_ 2334453406 M2P_SOE_Charge_B3 1023 "Null" ;
VAL_ 2334453406 M2P_SOE_Discharge_B3 1023 "Null" ;
VAL_ 2334453407 M2P_SOE_Charge_B3 1023 "Null" ;
VAL_ 2334453407 M2P_SOE_Discharge_B3 1023 "Null" ;
VAL_ 2334453408 M2P_SOE_Charge_B3 1023 "Null" ;
VAL_ 2334453408 M2P_SOE_Discharge_B3 1023 "Null" ;
VAL_ 2334453409 M2P_SOE_Charge_B3 1023 "Null" ;
VAL_ 2334453409 M2P_SOE_Discharge_B3 1023 "Null" ;
VAL_ 2334453410 M2P_SOE_Charge_B3 1023 "Null" ;
VAL_ 2334453410 M2P_SOE_Discharge_B3 1023 "Null" ;
VAL_ 2334453411 M2P_SOE_Charge_B3 1023 "Null" ;
VAL_ 2334453411 M2P_SOE_Discharge_B3 1023 "Null" ;
VAL_ 2334453412 M2P_SOE_Charge_B3 1023 "Null" ;
VAL_ 2334453412 M2P_SOE_Discharge_B3 1023 "Null" ;
VAL_ 2334453413 M2P_SOE_Charge_B3 1023 "Null" ;
VAL_ 2334453413 M2P_SOE_Discharge_B3 1023 "Null" ;
VAL_ 2334453414 M2P_SOE_Charge_B3 1023 "Null" ;
VAL_ 2334453414 M2P_SOE_Discharge_B3 1023 "Null" ;
VAL_ 2334453415 M2P_SOE_Charge_B3 1023 "Null" ;
VAL_ 2334453415 M2P_SOE_Discharge_B3 1023 "Null" ;
VAL_ 2334453416 M2P_SOE_Charge_B3 1023 "Null" ;
VAL_ 2334453416 M2P_SOE_Discharge_B3 1023 "Null" ;
VAL_ 2334453417 M2P_SOE_Charge_B3 1023 "Null" ;
VAL_ 2334453417 M2P_SOE_Discharge_B3 1023 "Null" ;
VAL_ 2334453418 M2P_SOE_Charge_B3 1023 "Null" ;
VAL_ 2334453418 M2P_SOE_Discharge_B3 1023 "Null" ;
VAL_ 2334453419 M2P_SOE_Charge_B3 1023 "Null" ;
VAL_ 2334453419 M2P_SOE_Discharge_B3 1023 "Null" ;
VAL_ 2334453420 M2P_SOE_Charge_B3 1023 "Null" ;
VAL_ 2334453420 M2P_SOE_Discharge_B3 1023 "Null" ;
VAL_ 2334453421 M2P_SOE_Charge_B3 1023 "Null" ;
VAL_ 2334453421 M2P_SOE_Discharge_B3 1023 "Null" ;
VAL_ 2334453422 M2P_SOE_Charge_B3 1023 "Null" ;
VAL_ 2334453422 M2P_SOE_Discharge_B3 1023 "Null" ;
VAL_ 2334453423 M2P_SOE_Charge_B3 1023 "Null" ;
VAL_ 2334453423 M2P_SOE_Discharge_B3 1023 "Null" ;
VAL_ 2334518929 M2P_Measure_Vol_B4_01 65535 "Invalid" ;
VAL_ 2334518929 M2P_Current_B4_01 65535 "Invalid" ;
VAL_ 2334518929 M2P_PermitMaxCharge_I_B4_01 65535 "Invalid" ;
VAL_ 2334518929 M2P_PermitMaxDisCharge_I_B4_01 65535 "Invalid" ;
VAL_ 2334518930 M2P_Measure_Vol_B4_02 65535 "Invalid" ;
VAL_ 2334518930 M2P_Current_B4_02 65535 "Invalid" ;
VAL_ 2334518930 M2P_PermitMaxCharge_I_B4_02 65535 "Invalid" ;
VAL_ 2334518930 M2P_PermitMaxDisCharge_I_B4_02 65535 "Invalid" ;
VAL_ 2334518931 M2P_Measure_Vol_B4_03 65535 "Invalid" ;
VAL_ 2334518931 M2P_Current_B4_03 65535 "Invalid" ;
VAL_ 2334518931 M2P_PermitMaxCharge_I_B4_03 65535 "Invalid" ;
VAL_ 2334518931 M2P_PermitMaxDisCharge_I_B4_03 65535 "Invalid" ;
VAL_ 2334518932 M2P_Measure_Vol_B4_04 65535 "Invalid" ;
VAL_ 2334518932 M2P_Current_B4_04 65535 "Invalid" ;
VAL_ 2334518932 M2P_PermitMaxCharge_I_B4_04 65535 "Invalid" ;
VAL_ 2334518932 M2P_PermitMaxDisCharge_I_B4_04 65535 "Invalid" ;
VAL_ 2334518933 M2P_Measure_Vol_B4_05 65535 "Invalid" ;
VAL_ 2334518933 M2P_Current_B4_05 65535 "Invalid" ;
VAL_ 2334518933 M2P_PermitMaxCharge_I_B4_05 65535 "Invalid" ;
VAL_ 2334518933 M2P_PermitMaxDisCharge_I_B4_05 65535 "Invalid" ;
VAL_ 2334518934 M2P_Measure_Vol_B4_06 65535 "Invalid" ;
VAL_ 2334518934 M2P_Current_B4_06 65535 "Invalid" ;
VAL_ 2334518934 M2P_PermitMaxCharge_I_B4_06 65535 "Invalid" ;
VAL_ 2334518934 M2P_PermitMaxDisCharge_I_B4_06 65535 "Invalid" ;
VAL_ 2334518935 M2P_Measure_Vol_B4_07 65535 "Invalid" ;
VAL_ 2334518935 M2P_Current_B4_07 65535 "Invalid" ;
VAL_ 2334518935 M2P_PermitMaxCharge_I_B4_07 65535 "Invalid" ;
VAL_ 2334518935 M2P_PermitMaxDisCharge_I_B4_07 65535 "Invalid" ;
VAL_ 2334518936 M2P_Measure_Vol_B4_08 65535 "Invalid" ;
VAL_ 2334518936 M2P_Current_B4_08 65535 "Invalid" ;
VAL_ 2334518936 M2P_PermitMaxCharge_I_B4_08 65535 "Invalid" ;
VAL_ 2334518936 M2P_PermitMaxDisCharge_I_B4_08 65535 "Invalid" ;
VAL_ 2334518937 M2P_Measure_Vol_B4_09 65535 "Invalid" ;
VAL_ 2334518937 M2P_Current_B4_09 65535 "Invalid" ;
VAL_ 2334518937 M2P_PermitMaxCharge_I_B4_09 65535 "Invalid" ;
VAL_ 2334518937 M2P_PermitMaxDisCharge_I_B4_09 65535 "Invalid" ;
VAL_ 2334518938 M2P_Measure_Vol_B4_10 65535 "Invalid" ;
VAL_ 2334518938 M2P_Current_B4_10 65535 "Invalid" ;
VAL_ 2334518938 M2P_PermitMaxCharge_I_B4_10 65535 "Invalid" ;
VAL_ 2334518938 M2P_PermitMaxDisCharge_I_B4_10 65535 "Invalid" ;
VAL_ 2334518939 M2P_Measure_Vol_B4_11 65535 "Invalid" ;
VAL_ 2334518939 M2P_Current_B4_11 65535 "Invalid" ;
VAL_ 2334518939 M2P_PermitMaxCharge_I_B4_11 65535 "Invalid" ;
VAL_ 2334518939 M2P_PermitMaxDisCharge_I_B4_11 65535 "Invalid" ;
VAL_ 2334518940 M2P_Measure_Vol_B4_12 65535 "Invalid" ;
VAL_ 2334518940 M2P_Current_B4_12 65535 "Invalid" ;
VAL_ 2334518940 M2P_PermitMaxCharge_I_B4_12 65535 "Invalid" ;
VAL_ 2334518940 M2P_PermitMaxDisCharge_I_B4_12 65535 "Invalid" ;
VAL_ 2334518941 M2P_Measure_Vol_B4_13 65535 "Invalid" ;
VAL_ 2334518941 M2P_Current_B4_13 65535 "Invalid" ;
VAL_ 2334518941 M2P_PermitMaxCharge_I_B4_13 65535 "Invalid" ;
VAL_ 2334518941 M2P_PermitMaxDisCharge_I_B4_13 65535 "Invalid" ;
VAL_ 2334518942 M2P_Measure_Vol_B4_14 65535 "Invalid" ;
VAL_ 2334518942 M2P_Current_B4_14 65535 "Invalid" ;
VAL_ 2334518942 M2P_PermitMaxCharge_I_B4_14 65535 "Invalid" ;
VAL_ 2334518942 M2P_PermitMaxDisCharge_I_B4_14 65535 "Invalid" ;
VAL_ 2334518943 M2P_Measure_Vol_B4_15 65535 "Invalid" ;
VAL_ 2334518943 M2P_Current_B4_15 65535 "Invalid" ;
VAL_ 2334518943 M2P_PermitMaxCharge_I_B4_15 65535 "Invalid" ;
VAL_ 2334518943 M2P_PermitMaxDisCharge_I_B4_15 65535 "Invalid" ;
VAL_ 2334518944 M2P_Measure_Vol_B4_16 65535 "Invalid" ;
VAL_ 2334518944 M2P_Current_B4_16 65535 "Invalid" ;
VAL_ 2334518944 M2P_PermitMaxCharge_I_B4_16 65535 "Invalid" ;
VAL_ 2334518944 M2P_PermitMaxDisCharge_I_B4_16 65535 "Invalid" ;
VAL_ 2334518945 M2P_Measure_Vol_B4_17 65535 "Invalid" ;
VAL_ 2334518945 M2P_Current_B4_17 65535 "Invalid" ;
VAL_ 2334518945 M2P_PermitMaxCharge_I_B4_17 65535 "Invalid" ;
VAL_ 2334518945 M2P_PermitMaxDisCharge_I_B4_17 65535 "Invalid" ;
VAL_ 2334518946 M2P_Measure_Vol_B4_18 65535 "Invalid" ;
VAL_ 2334518946 M2P_Current_B4_18 65535 "Invalid" ;
VAL_ 2334518946 M2P_PermitMaxCharge_I_B4_18 65535 "Invalid" ;
VAL_ 2334518946 M2P_PermitMaxDisCharge_I_B4_18 65535 "Invalid" ;
VAL_ 2334518947 M2P_Measure_Vol_B4_19 65535 "Invalid" ;
VAL_ 2334518947 M2P_Current_B4_19 65535 "Invalid" ;
VAL_ 2334518947 M2P_PermitMaxCharge_I_B4_19 65535 "Invalid" ;
VAL_ 2334518947 M2P_PermitMaxDisCharge_I_B4_19 65535 "Invalid" ;
VAL_ 2334518948 M2P_Measure_Vol_B4_20 65535 "Invalid" ;
VAL_ 2334518948 M2P_Current_B4_20 65535 "Invalid" ;
VAL_ 2334518948 M2P_PermitMaxCharge_I_B4_20 65535 "Invalid" ;
VAL_ 2334518948 M2P_PermitMaxDisCharge_I_B4_20 65535 "Invalid" ;
VAL_ 2334518949 M2P_Measure_Vol_B4_21 65535 "Invalid" ;
VAL_ 2334518949 M2P_Current_B4_21 65535 "Invalid" ;
VAL_ 2334518949 M2P_PermitMaxCharge_I_B4_21 65535 "Invalid" ;
VAL_ 2334518949 M2P_PermitMaxDisCharge_I_B4_21 65535 "Invalid" ;
VAL_ 2334518950 M2P_Measure_Vol_B4_22 65535 "Invalid" ;
VAL_ 2334518950 M2P_Current_B4_22 65535 "Invalid" ;
VAL_ 2334518950 M2P_PermitMaxCharge_I_B4_22 65535 "Invalid" ;
VAL_ 2334518950 M2P_PermitMaxDisCharge_I_B4_22 65535 "Invalid" ;
VAL_ 2334518951 M2P_Measure_Vol_B4_23 65535 "Invalid" ;
VAL_ 2334518951 M2P_Current_B4_23 65535 "Invalid" ;
VAL_ 2334518951 M2P_PermitMaxCharge_I_B4_23 65535 "Invalid" ;
VAL_ 2334518951 M2P_PermitMaxDisCharge_I_B4_23 65535 "Invalid" ;
VAL_ 2334518952 M2P_Measure_Vol_B4_24 65535 "Invalid" ;
VAL_ 2334518952 M2P_Current_B4_24 65535 "Invalid" ;
VAL_ 2334518952 M2P_PermitMaxCharge_I_B4_24 65535 "Invalid" ;
VAL_ 2334518952 M2P_PermitMaxDisCharge_I_B4_24 65535 "Invalid" ;
VAL_ 2334518953 M2P_Measure_Vol_B4_25 65535 "Invalid" ;
VAL_ 2334518953 M2P_Current_B4_25 65535 "Invalid" ;
VAL_ 2334518953 M2P_PermitMaxCharge_I_B4_25 65535 "Invalid" ;
VAL_ 2334518953 M2P_PermitMaxDisCharge_I_B4_25 65535 "Invalid" ;
VAL_ 2334518954 M2P_Measure_Vol_B4_26 65535 "Invalid" ;
VAL_ 2334518954 M2P_Current_B4_26 65535 "Invalid" ;
VAL_ 2334518954 M2P_PermitMaxCharge_I_B4_26 65535 "Invalid" ;
VAL_ 2334518954 M2P_PermitMaxDisCharge_I_B4_26 65535 "Invalid" ;
VAL_ 2334518955 M2P_Measure_Vol_B4_27 65535 "Invalid" ;
VAL_ 2334518955 M2P_Current_B4_27 65535 "Invalid" ;
VAL_ 2334518955 M2P_PermitMaxCharge_I_B4_27 65535 "Invalid" ;
VAL_ 2334518955 M2P_PermitMaxDisCharge_I_B4_27 65535 "Invalid" ;
VAL_ 2334518956 M2P_Measure_Vol_B4_28 65535 "Invalid" ;
VAL_ 2334518956 M2P_Current_B4_28 65535 "Invalid" ;
VAL_ 2334518956 M2P_PermitMaxCharge_I_B4_28 65535 "Invalid" ;
VAL_ 2334518956 M2P_PermitMaxDisCharge_I_B4_28 65535 "Invalid" ;
VAL_ 2334518957 M2P_Measure_Vol_B4_29 65535 "Invalid" ;
VAL_ 2334518957 M2P_Current_B4_29 65535 "Invalid" ;
VAL_ 2334518957 M2P_PermitMaxCharge_I_B4_29 65535 "Invalid" ;
VAL_ 2334518957 M2P_PermitMaxDisCharge_I_B4_29 65535 "Invalid" ;
VAL_ 2334518958 M2P_Measure_Vol_B4_30 65535 "Invalid" ;
VAL_ 2334518958 M2P_Current_B4_30 65535 "Invalid" ;
VAL_ 2334518958 M2P_PermitMaxCharge_I_B4_30 65535 "Invalid" ;
VAL_ 2334518958 M2P_PermitMaxDisCharge_I_B4_30 65535 "Invalid" ;
VAL_ 2334518959 M2P_Measure_Vol_B4_31 65535 "Invalid" ;
VAL_ 2334518959 M2P_Current_B4_31 65535 "Invalid" ;
VAL_ 2334518959 M2P_PermitMaxCharge_I_B4_31 65535 "Invalid" ;
VAL_ 2334518959 M2P_PermitMaxDisCharge_I_B4_31 65535 "Invalid" ;
VAL_ 2334650001 M2P_SysremEngy_Chg_B4_01 65535 "Invalid" ;
VAL_ 2334650001 M2P_SysremEngy_DisChg_B4_01 65535 "Invalid" ;
VAL_ 2334650002 M2P_SysremEngy_Chg_B4_02 65535 "Invalid" ;
VAL_ 2334650002 M2P_SysremEngy_DisChg_B4_02 65535 "Invalid" ;
VAL_ 2334650003 M2P_SysremEngy_Chg_B4_03 65535 "Invalid" ;
VAL_ 2334650003 M2P_SysremEngy_DisChg_B4_03 65535 "Invalid" ;
VAL_ 2334650004 M2P_SysremEngy_Chg_B4_04 65535 "Invalid" ;
VAL_ 2334650004 M2P_SysremEngy_DisChg_B4_04 65535 "Invalid" ;
VAL_ 2334650005 M2P_SysremEngy_Chg_B4_05 65535 "Invalid" ;
VAL_ 2334650005 M2P_SysremEngy_DisChg_B4_05 65535 "Invalid" ;
VAL_ 2334650006 M2P_SysremEngy_Chg_B4_06 65535 "Invalid" ;
VAL_ 2334650006 M2P_SysremEngy_DisChg_B4_06 65535 "Invalid" ;
VAL_ 2334650007 M2P_SysremEngy_Chg_B4_07 65535 "Invalid" ;
VAL_ 2334650007 M2P_SysremEngy_DisChg_B4_07 65535 "Invalid" ;
VAL_ 2334650008 M2P_SysremEngy_Chg_B4_08 65535 "Invalid" ;
VAL_ 2334650008 M2P_SysremEngy_DisChg_B4_08 65535 "Invalid" ;
VAL_ 2334650009 M2P_SysremEngy_Chg_B4_09 65535 "Invalid" ;
VAL_ 2334650009 M2P_SysremEngy_DisChg_B4_09 65535 "Invalid" ;
VAL_ 2334650010 M2P_SysremEngy_Chg_B4_10 65535 "Invalid" ;
VAL_ 2334650010 M2P_SysremEngy_DisChg_B4_10 65535 "Invalid" ;
VAL_ 2334650011 M2P_SysremEngy_Chg_B4_11 65535 "Invalid" ;
VAL_ 2334650011 M2P_SysremEngy_DisChg_B4_11 65535 "Invalid" ;
VAL_ 2334650012 M2P_SysremEngy_Chg_B4_12 65535 "Invalid" ;
VAL_ 2334650012 M2P_SysremEngy_DisChg_B4_12 65535 "Invalid" ;
VAL_ 2334650013 M2P_SysremEngy_Chg_B4_13 65535 "Invalid" ;
VAL_ 2334650013 M2P_SysremEngy_DisChg_B4_13 65535 "Invalid" ;
VAL_ 2334650014 M2P_SysremEngy_Chg_B4_14 65535 "Invalid" ;
VAL_ 2334650014 M2P_SysremEngy_DisChg_B4_14 65535 "Invalid" ;
VAL_ 2334650015 M2P_SysremEngy_Chg_B4_15 65535 "Invalid" ;
VAL_ 2334650015 M2P_SysremEngy_DisChg_B4_15 65535 "Invalid" ;
VAL_ 2334650016 M2P_SysremEngy_Chg_B4_16 65535 "Invalid" ;
VAL_ 2334650016 M2P_SysremEngy_DisChg_B4_16 65535 "Invalid" ;
VAL_ 2334650017 M2P_SysremEngy_Chg_B4_17 65535 "Invalid" ;
VAL_ 2334650017 M2P_SysremEngy_DisChg_B4_17 65535 "Invalid" ;
VAL_ 2334650018 M2P_SysremEngy_Chg_B4_18 65535 "Invalid" ;
VAL_ 2334650018 M2P_SysremEngy_DisChg_B4_18 65535 "Invalid" ;
VAL_ 2334650019 M2P_SysremEngy_Chg_B4_19 65535 "Invalid" ;
VAL_ 2334650019 M2P_SysremEngy_DisChg_B4_19 65535 "Invalid" ;
VAL_ 2334650020 M2P_SysremEngy_Chg_B4_20 65535 "Invalid" ;
VAL_ 2334650020 M2P_SysremEngy_DisChg_B4_20 65535 "Invalid" ;
VAL_ 2334650021 M2P_SysremEngy_Chg_B4_21 65535 "Invalid" ;
VAL_ 2334650021 M2P_SysremEngy_DisChg_B4_21 65535 "Invalid" ;
VAL_ 2334650022 M2P_SysremEngy_Chg_B4_22 65535 "Invalid" ;
VAL_ 2334650022 M2P_SysremEngy_DisChg_B4_22 65535 "Invalid" ;
VAL_ 2334650023 M2P_SysremEngy_Chg_B4_23 65535 "Invalid" ;
VAL_ 2334650023 M2P_SysremEngy_DisChg_B4_23 65535 "Invalid" ;
VAL_ 2334650024 M2P_SysremEngy_Chg_B4_24 65535 "Invalid" ;
VAL_ 2334650024 M2P_SysremEngy_DisChg_B4_24 65535 "Invalid" ;
VAL_ 2334650025 M2P_SysremEngy_Chg_B4_25 65535 "Invalid" ;
VAL_ 2334650025 M2P_SysremEngy_DisChg_B4_25 65535 "Invalid" ;
VAL_ 2334650026 M2P_SysremEngy_Chg_B4_26 65535 "Invalid" ;
VAL_ 2334650026 M2P_SysremEngy_DisChg_B4_26 65535 "Invalid" ;
VAL_ 2334650027 M2P_SysremEngy_Chg_B4_27 65535 "Invalid" ;
VAL_ 2334650027 M2P_SysremEngy_DisChg_B4_27 65535 "Invalid" ;
VAL_ 2334650028 M2P_SysremEngy_Chg_B4_28 65535 "Invalid" ;
VAL_ 2334650028 M2P_SysremEngy_DisChg_B4_28 65535 "Invalid" ;
VAL_ 2334650029 M2P_SysremEngy_Chg_B4_29 65535 "Invalid" ;
VAL_ 2334650029 M2P_SysremEngy_DisChg_B4_29 65535 "Invalid" ;
VAL_ 2334650030 M2P_SysremEngy_Chg_B4_30 65535 "Invalid" ;
VAL_ 2334650030 M2P_SysremEngy_DisChg_B4_30 65535 "Invalid" ;
VAL_ 2334650031 M2P_SysremEngy_Chg_B4_31 65535 "Invalid" ;
VAL_ 2334650031 M2P_SysremEngy_DisChg_B4_31 65535 "Invalid" ;
VAL_ 2334715537 M2P_BMS_Status_B4 0 "初始化状态" 1 "非满充满放状态" 2 "满充状态" 3 "满放状态" ;
VAL_ 2334715537 M2P_SOC_B4 1023 "Null" ;
VAL_ 2334715537 M2P_SOH_B4 255 "Null" ;
VAL_ 2334715538 M2P_BMS_Status_B4 0 "初始化状态" 1 "非满充满放状态" 2 "满充状态" 3 "满放状态" ;
VAL_ 2334715538 M2P_SOC_B4 1023 "Null" ;
VAL_ 2334715538 M2P_SOH_B4 255 "Null" ;
VAL_ 2334715539 M2P_BMS_Status_B4 0 "初始化状态" 1 "非满充满放状态" 2 "满充状态" 3 "满放状态" ;
VAL_ 2334715539 M2P_SOC_B4 1023 "Null" ;
VAL_ 2334715539 M2P_SOH_B4 255 "Null" ;
VAL_ 2334715540 M2P_BMS_Status_B4 0 "初始化状态" 1 "非满充满放状态" 2 "满充状态" 3 "满放状态" ;
VAL_ 2334715540 M2P_SOC_B4 1023 "Null" ;
VAL_ 2334715540 M2P_SOH_B4 255 "Null" ;
VAL_ 2334715541 M2P_BMS_Status_B4 0 "初始化状态" 1 "非满充满放状态" 2 "满充状态" 3 "满放状态" ;
VAL_ 2334715541 M2P_SOC_B4 1023 "Null" ;
VAL_ 2334715541 M2P_SOH_B4 255 "Null" ;
VAL_ 2334715542 M2P_BMS_Status_B4 0 "初始化状态" 1 "非满充满放状态" 2 "满充状态" 3 "满放状态" ;
VAL_ 2334715542 M2P_SOC_B4 1023 "Null" ;
VAL_ 2334715542 M2P_SOH_B4 255 "Null" ;
VAL_ 2334715543 M2P_BMS_Status_B4 0 "初始化状态" 1 "非满充满放状态" 2 "满充状态" 3 "满放状态" ;
VAL_ 2334715543 M2P_SOC_B4 1023 "Null" ;
VAL_ 2334715543 M2P_SOH_B4 255 "Null" ;
VAL_ 2334715544 M2P_BMS_Status_B4 0 "初始化状态" 1 "非满充满放状态" 2 "满充状态" 3 "满放状态" ;
VAL_ 2334715544 M2P_SOC_B4 1023 "Null" ;
VAL_ 2334715544 M2P_SOH_B4 255 "Null" ;
VAL_ 2334715545 M2P_BMS_Status_B4 0 "初始化状态" 1 "非满充满放状态" 2 "满充状态" 3 "满放状态" ;
VAL_ 2334715545 M2P_SOC_B4 1023 "Null" ;
VAL_ 2334715545 M2P_SOH_B4 255 "Null" ;
VAL_ 2334715546 M2P_BMS_Status_B4 0 "初始化状态" 1 "非满充满放状态" 2 "满充状态" 3 "满放状态" ;
VAL_ 2334715546 M2P_SOC_B4 1023 "Null" ;
VAL_ 2334715546 M2P_SOH_B4 255 "Null" ;
VAL_ 2334715547 M2P_BMS_Status_B4 0 "初始化状态" 1 "非满充满放状态" 2 "满充状态" 3 "满放状态" ;
VAL_ 2334715547 M2P_SOC_B4 1023 "Null" ;
VAL_ 2334715547 M2P_SOH_B4 255 "Null" ;
VAL_ 2334715548 M2P_BMS_Status_B4 0 "初始化状态" 1 "非满充满放状态" 2 "满充状态" 3 "满放状态" ;
VAL_ 2334715548 M2P_SOC_B4 1023 "Null" ;
VAL_ 2334715548 M2P_SOH_B4 255 "Null" ;
VAL_ 2334715549 M2P_BMS_Status_B4 0 "初始化状态" 1 "非满充满放状态" 2 "满充状态" 3 "满放状态" ;
VAL_ 2334715549 M2P_SOC_B4 1023 "Null" ;
VAL_ 2334715549 M2P_SOH_B4 255 "Null" ;
VAL_ 2334715550 M2P_BMS_Status_B4 0 "初始化状态" 1 "非满充满放状态" 2 "满充状态" 3 "满放状态" ;
VAL_ 2334715550 M2P_SOC_B4 1023 "Null" ;
VAL_ 2334715550 M2P_SOH_B4 255 "Null" ;
VAL_ 2334715551 M2P_BMS_Status_B4 0 "初始化状态" 1 "非满充满放状态" 2 "满充状态" 3 "满放状态" ;
VAL_ 2334715551 M2P_SOC_B4 1023 "Null" ;
VAL_ 2334715551 M2P_SOH_B4 255 "Null" ;
VAL_ 2334715552 M2P_BMS_Status_B4 0 "初始化状态" 1 "非满充满放状态" 2 "满充状态" 3 "满放状态" ;
VAL_ 2334715552 M2P_SOC_B4 1023 "Null" ;
VAL_ 2334715552 M2P_SOH_B4 255 "Null" ;
VAL_ 2334715553 M2P_BMS_Status_B4 0 "初始化状态" 1 "非满充满放状态" 2 "满充状态" 3 "满放状态" ;
VAL_ 2334715553 M2P_SOC_B4 1023 "Null" ;
VAL_ 2334715553 M2P_SOH_B4 255 "Null" ;
VAL_ 2334715554 M2P_BMS_Status_B4 0 "初始化状态" 1 "非满充满放状态" 2 "满充状态" 3 "满放状态" ;
VAL_ 2334715554 M2P_SOC_B4 1023 "Null" ;
VAL_ 2334715554 M2P_SOH_B4 255 "Null" ;
VAL_ 2334715555 M2P_BMS_Status_B4 0 "初始化状态" 1 "非满充满放状态" 2 "满充状态" 3 "满放状态" ;
VAL_ 2334715555 M2P_SOC_B4 1023 "Null" ;
VAL_ 2334715555 M2P_SOH_B4 255 "Null" ;
VAL_ 2334715556 M2P_BMS_Status_B4 0 "初始化状态" 1 "非满充满放状态" 2 "满充状态" 3 "满放状态" ;
VAL_ 2334715556 M2P_SOC_B4 1023 "Null" ;
VAL_ 2334715556 M2P_SOH_B4 255 "Null" ;
VERSION ""

NS_ :

BS_:

BU_: MBMU PC SBMU IMM ETH DCDC LEMS

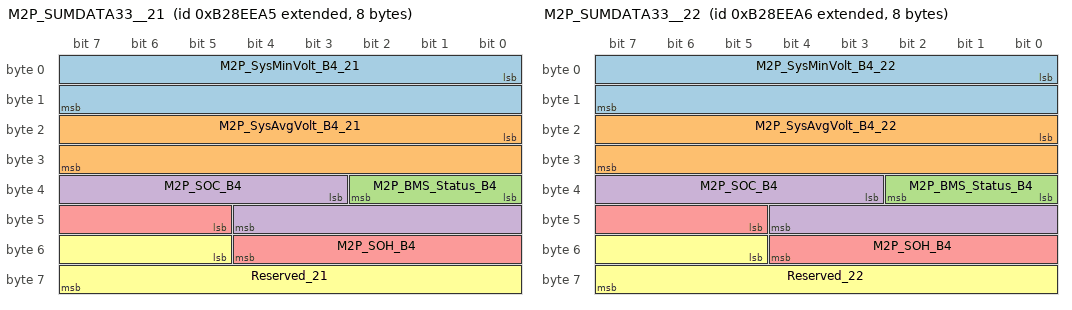
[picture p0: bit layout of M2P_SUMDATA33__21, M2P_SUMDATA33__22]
BO_ 2334715557 M2P_SUMDATA33__21: 8 MBMU
 SG_ M2P_SysMinVolt_B4_21 : 0|16@1+ (1,0) [0|65535] "mv"  PC
 SG_ M2P_SysAvgVolt_B4_21 : 16|16@1+ (1,0) [0|65535] "mv"  PC
 SG_ M2P_BMS_Status_B4 : 32|3@1+ (1,0) [0|7] ""  PC
 SG_ M2P_SOC_B4 : 35|10@1+ (0.1,0) [0|102.3] "%"  PC
 SG_ M2P_SOH_B4 : 45|8@1+ (1,0) [0|255] "%"  PC
 SG_ Reserved_21 : 53|11@1+ (1,0) [0|2047] ""  PC

BO_ 2334715558 M2P_SUMDATA33__22: 8 MBMU
 SG_ M2P_SysMinVolt_B4_22 : 0|16@1+ (1,0) [0|65535] "mv"  PC
 SG_ M2P_SysAvgVolt_B4_22 : 16|16@1+ (1,0) [0|65535] "mv"  PC
 SG_ M2P_BMS_Status_B4 : 32|3@1+ (1,0) [0|7] ""  PC
 SG_ M2P_SOC_B4 : 35|10@1+ (0.1,0) [0|102.3] "%"  PC
 SG_ M2P_SOH_B4 : 45|8@1+ (1,0) [0|255] "%"  PC
 SG_ Reserved_22 : 53|11@1+ (1,0) [0|2047] ""  PC

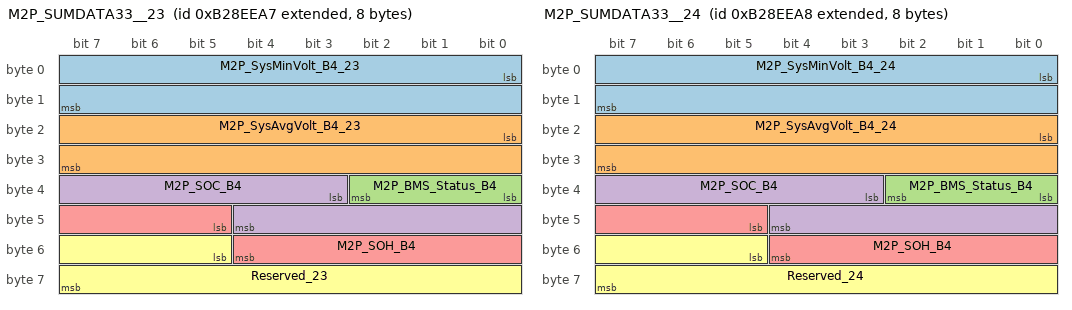
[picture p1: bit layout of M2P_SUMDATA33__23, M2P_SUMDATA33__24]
BO_ 2334715559 M2P_SUMDATA33__23: 8 MBMU
 SG_ M2P_SysMinVolt_B4_23 : 0|16@1+ (1,0) [0|65535] "mv"  PC
 SG_ M2P_SysAvgVolt_B4_23 : 16|16@1+ (1,0) [0|65535] "mv"  PC
 SG_ M2P_BMS_Status_B4 : 32|3@1+ (1,0) [0|7] ""  PC
 SG_ M2P_SOC_B4 : 35|10@1+ (0.1,0) [0|102.3] "%"  PC
 SG_ M2P_SOH_B4 : 45|8@1+ (1,0) [0|255] "%"  PC
 SG_ Reserved_23 : 53|11@1+ (1,0) [0|2047] ""  PC

BO_ 2334715560 M2P_SUMDATA33__24: 8 MBMU
 SG_ M2P_SysMinVolt_B4_24 : 0|16@1+ (1,0) [0|65535] "mv"  PC
 SG_ M2P_SysAvgVolt_B4_24 : 16|16@1+ (1,0) [0|65535] "mv"  PC
 SG_ M2P_BMS_Status_B4 : 32|3@1+ (1,0) [0|7] ""  PC
 SG_ M2P_SOC_B4 : 35|10@1+ (0.1,0) [0|102.3] "%"  PC
 SG_ M2P_SOH_B4 : 45|8@1+ (1,0) [0|255] "%"  PC
 SG_ Reserved_24 : 53|11@1+ (1,0) [0|2047] ""  PC

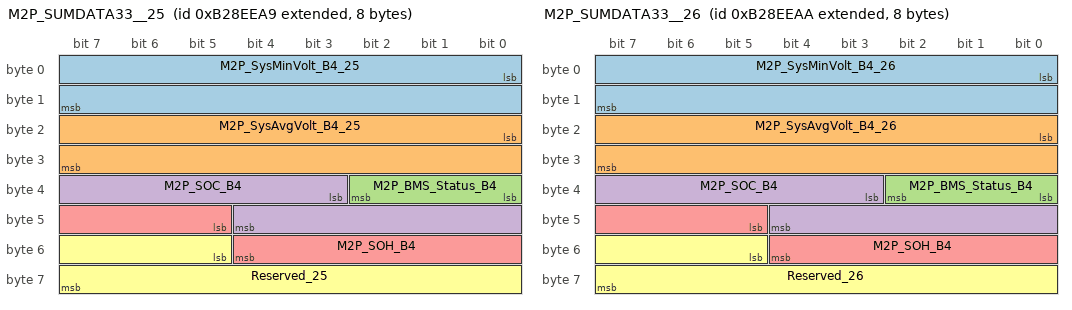
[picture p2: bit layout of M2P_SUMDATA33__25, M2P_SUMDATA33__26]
BO_ 2334715561 M2P_SUMDATA33__25: 8 MBMU
 SG_ M2P_SysMinVolt_B4_25 : 0|16@1+ (1,0) [0|65535] "mv"  PC
 SG_ M2P_SysAvgVolt_B4_25 : 16|16@1+ (1,0) [0|65535] "mv"  PC
 SG_ M2P_BMS_Status_B4 : 32|3@1+ (1,0) [0|7] ""  PC
 SG_ M2P_SOC_B4 : 35|10@1+ (0.1,0) [0|102.3] "%"  PC
 SG_ M2P_SOH_B4 : 45|8@1+ (1,0) [0|255] "%"  PC
 SG_ Reserved_25 : 53|11@1+ (1,0) [0|2047] ""  PC

BO_ 2334715562 M2P_SUMDATA33__26: 8 MBMU
 SG_ M2P_SysMinVolt_B4_26 : 0|16@1+ (1,0) [0|65535] "mv"  PC
 SG_ M2P_SysAvgVolt_B4_26 : 16|16@1+ (1,0) [0|65535] "mv"  PC
 SG_ M2P_BMS_Status_B4 : 32|3@1+ (1,0) [0|7] ""  PC
 SG_ M2P_SOC_B4 : 35|10@1+ (0.1,0) [0|102.3] "%"  PC
 SG_ M2P_SOH_B4 : 45|8@1+ (1,0) [0|255] "%"  PC
 SG_ Reserved_26 : 53|11@1+ (1,0) [0|2047] ""  PC

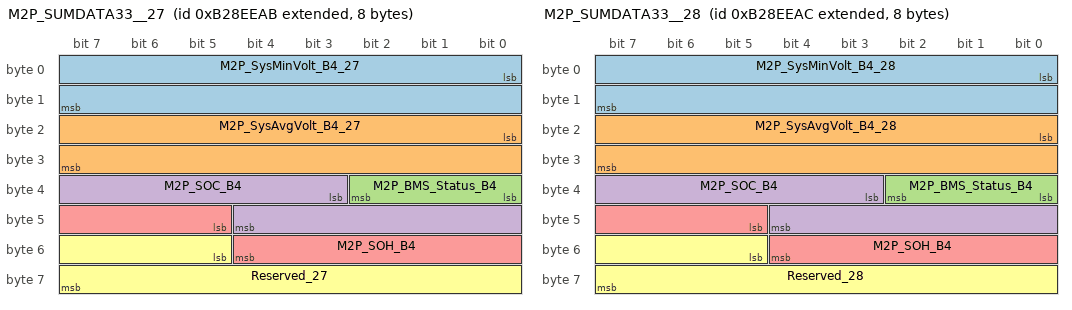
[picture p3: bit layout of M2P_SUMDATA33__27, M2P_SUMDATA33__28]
BO_ 2334715563 M2P_SUMDATA33__27: 8 MBMU
 SG_ M2P_SysMinVolt_B4_27 : 0|16@1+ (1,0) [0|65535] "mv"  PC
 SG_ M2P_SysAvgVolt_B4_27 : 16|16@1+ (1,0) [0|65535] "mv"  PC
 SG_ M2P_BMS_Status_B4 : 32|3@1+ (1,0) [0|7] ""  PC
 SG_ M2P_SOC_B4 : 35|10@1+ (0.1,0) [0|102.3] "%"  PC
 SG_ M2P_SOH_B4 : 45|8@1+ (1,0) [0|255] "%"  PC
 SG_ Reserved_27 : 53|11@1+ (1,0) [0|2047] ""  PC

BO_ 2334715564 M2P_SUMDATA33__28: 8 MBMU
 SG_ M2P_SysMinVolt_B4_28 : 0|16@1+ (1,0) [0|65535] "mv"  PC
 SG_ M2P_SysAvgVolt_B4_28 : 16|16@1+ (1,0) [0|65535] "mv"  PC
 SG_ M2P_BMS_Status_B4 : 32|3@1+ (1,0) [0|7] ""  PC
 SG_ M2P_SOC_B4 : 35|10@1+ (0.1,0) [0|102.3] "%"  PC
 SG_ M2P_SOH_B4 : 45|8@1+ (1,0) [0|255] "%"  PC
 SG_ Reserved_28 : 53|11@1+ (1,0) [0|2047] ""  PC

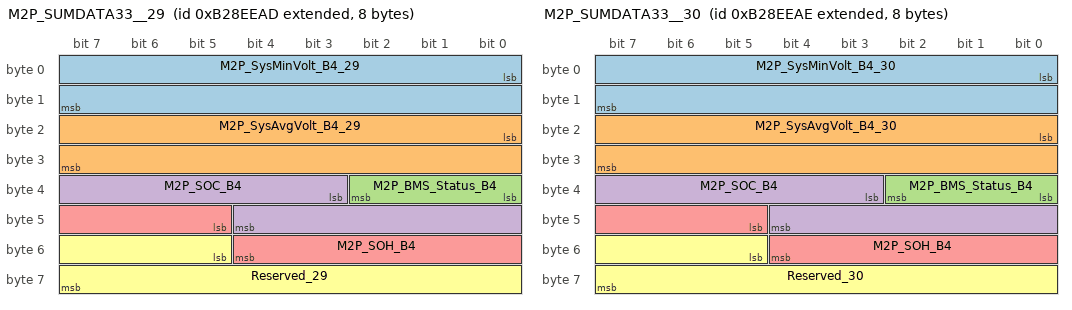
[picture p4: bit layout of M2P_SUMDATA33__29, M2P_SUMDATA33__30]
BO_ 2334715565 M2P_SUMDATA33__29: 8 MBMU
 SG_ M2P_SysMinVolt_B4_29 : 0|16@1+ (1,0) [0|65535] "mv"  PC
 SG_ M2P_SysAvgVolt_B4_29 : 16|16@1+ (1,0) [0|65535] "mv"  PC
 SG_ M2P_BMS_Status_B4 : 32|3@1+ (1,0) [0|7] ""  PC
 SG_ M2P_SOC_B4 : 35|10@1+ (0.1,0) [0|102.3] "%"  PC
 SG_ M2P_SOH_B4 : 45|8@1+ (1,0) [0|255] "%"  PC
 SG_ Reserved_29 : 53|11@1+ (1,0) [0|2047] ""  PC

BO_ 2334715566 M2P_SUMDATA33__30: 8 MBMU
 SG_ M2P_SysMinVolt_B4_30 : 0|16@1+ (1,0) [0|65535] "mv"  PC
 SG_ M2P_SysAvgVolt_B4_30 : 16|16@1+ (1,0) [0|65535] "mv"  PC
 SG_ M2P_BMS_Status_B4 : 32|3@1+ (1,0) [0|7] ""  PC
 SG_ M2P_SOC_B4 : 35|10@1+ (0.1,0) [0|102.3] "%"  PC
 SG_ M2P_SOH_B4 : 45|8@1+ (1,0) [0|255] "%"  PC
 SG_ Reserved_30 : 53|11@1+ (1,0) [0|2047] ""  PC

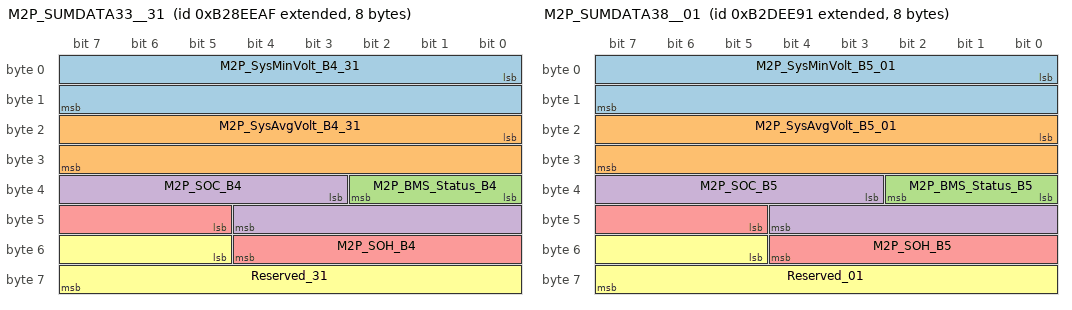
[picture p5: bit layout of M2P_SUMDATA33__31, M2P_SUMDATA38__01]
BO_ 2334715567 M2P_SUMDATA33__31: 8 MBMU
 SG_ M2P_SysMinVolt_B4_31 : 0|16@1+ (1,0) [0|65535] "mv"  PC
 SG_ M2P_SysAvgVolt_B4_31 : 16|16@1+ (1,0) [0|65535] "mv"  PC
 SG_ M2P_BMS_Status_B4 : 32|3@1+ (1,0) [0|7] ""  PC
 SG_ M2P_SOC_B4 : 35|10@1+ (0.1,0) [0|102.3] "%"  PC
 SG_ M2P_SOH_B4 : 45|8@1+ (1,0) [0|255] "%"  PC
 SG_ Reserved_31 : 53|11@1+ (1,0) [0|2047] ""  PC

BO_ 2334781073 M2P_SUMDATA34__01: 8 MBMU
 SG_ M2P_SOE_Charge_B4 : 0|10@1+ (0.1,0) [0|102.3] "%"  PC
 SG_ M2P_SOE_Discharge_B4 : 10|10@1+ (0.1,0) [0|102.3] "%"  PC
 SG_ Reserved_01 : 20|44@1+ (1,0) [0|17592186044415] ""  PC

BO_ 2334781074 M2P_SUMDATA34__02: 8 MBMU
 SG_ M2P_SOE_Charge_B4 : 0|10@1+ (0.1,0) [0|102.3] "%"  PC
 SG_ M2P_SOE_Discharge_B4 : 10|10@1+ (0.1,0) [0|102.3] "%"  PC
 SG_ Reserved_02 : 20|44@1+ (1,0) [0|17592186044415] ""  PC

BO_ 2334781075 M2P_SUMDATA34__03: 8 MBMU
 SG_ M2P_SOE_Charge_B4 : 0|10@1+ (0.1,0) [0|102.3] "%"  PC
 SG_ M2P_SOE_Discharge_B4 : 10|10@1+ (0.1,0) [0|102.3] "%"  PC
 SG_ Reserved_03 : 20|44@1+ (1,0) [0|17592186044415] ""  PC

BO_ 2334781076 M2P_SUMDATA34__04: 8 MBMU
 SG_ M2P_SOE_Charge_B4 : 0|10@1+ (0.1,0) [0|102.3] "%"  PC
 SG_ M2P_SOE_Discharge_B4 : 10|10@1+ (0.1,0) [0|102.3] "%"  PC
 SG_ Reserved_04 : 20|44@1+ (1,0) [0|17592186044415] ""  PC

BO_ 2334781077 M2P_SUMDATA34__05: 8 MBMU
 SG_ M2P_SOE_Charge_B4 : 0|10@1+ (0.1,0) [0|102.3] "%"  PC
 SG_ M2P_SOE_Discharge_B4 : 10|10@1+ (0.1,0) [0|102.3] "%"  PC
 SG_ Reserved_05 : 20|44@1+ (1,0) [0|17592186044415] ""  PC

BO_ 2334781078 M2P_SUMDATA34__06: 8 MBMU
 SG_ M2P_SOE_Charge_B4 : 0|10@1+ (0.1,0) [0|102.3] "%"  PC
 SG_ M2P_SOE_Discharge_B4 : 10|10@1+ (0.1,0) [0|102.3] "%"  PC
 SG_ Reserved_06 : 20|44@1+ (1,0) [0|17592186044415] ""  PC

BO_ 2334781079 M2P_SUMDATA34__07: 8 MBMU
 SG_ M2P_SOE_Charge_B4 : 0|10@1+ (0.1,0) [0|102.3] "%"  PC
 SG_ M2P_SOE_Discharge_B4 : 10|10@1+ (0.1,0) [0|102.3] "%"  PC
 SG_ Reserved_07 : 20|44@1+ (1,0) [0|17592186044415] ""  PC

BO_ 2334781080 M2P_SUMDATA34__08: 8 MBMU
 SG_ M2P_SOE_Charge_B4 : 0|10@1+ (0.1,0) [0|102.3] "%"  PC
 SG_ M2P_SOE_Discharge_B4 : 10|10@1+ (0.1,0) [0|102.3] "%"  PC
 SG_ Reserved_08 : 20|44@1+ (1,0) [0|17592186044415] ""  PC

BO_ 2334781081 M2P_SUMDATA34__09: 8 MBMU
 SG_ M2P_SOE_Charge_B4 : 0|10@1+ (0.1,0) [0|102.3] "%"  PC
 SG_ M2P_SOE_Discharge_B4 : 10|10@1+ (0.1,0) [0|102.3] "%"  PC
 SG_ Reserved_09 : 20|44@1+ (1,0) [0|17592186044415] ""  PC

BO_ 2334781082 M2P_SUMDATA34__10: 8 MBMU
 SG_ M2P_SOE_Charge_B4 : 0|10@1+ (0.1,0) [0|102.3] "%"  PC
 SG_ M2P_SOE_Discharge_B4 : 10|10@1+ (0.1,0) [0|102.3] "%"  PC
 SG_ Reserved_10 : 20|44@1+ (1,0) [0|17592186044415] ""  PC

BO_ 2334781083 M2P_SUMDATA34__11: 8 MBMU
 SG_ M2P_SOE_Charge_B4 : 0|10@1+ (0.1,0) [0|102.3] "%"  PC
 SG_ M2P_SOE_Discharge_B4 : 10|10@1+ (0.1,0) [0|102.3] "%"  PC
 SG_ Reserved_11 : 20|44@1+ (1,0) [0|17592186044415] ""  PC

BO_ 2334781084 M2P_SUMDATA34__12: 8 MBMU
 SG_ M2P_SOE_Charge_B4 : 0|10@1+ (0.1,0) [0|102.3] "%"  PC
 SG_ M2P_SOE_Discharge_B4 : 10|10@1+ (0.1,0) [0|102.3] "%"  PC
 SG_ Reserved_12 : 20|44@1+ (1,0) [0|17592186044415] ""  PC

BO_ 2334781085 M2P_SUMDATA34__13: 8 MBMU
 SG_ M2P_SOE_Charge_B4 : 0|10@1+ (0.1,0) [0|102.3] "%"  PC
 SG_ M2P_SOE_Discharge_B4 : 10|10@1+ (0.1,0) [0|102.3] "%"  PC
 SG_ Reserved_13 : 20|44@1+ (1,0) [0|17592186044415] ""  PC

BO_ 2334781086 M2P_SUMDATA34__14: 8 MBMU
 SG_ M2P_SOE_Charge_B4 : 0|10@1+ (0.1,0) [0|102.3] "%"  PC
 SG_ M2P_SOE_Discharge_B4 : 10|10@1+ (0.1,0) [0|102.3] "%"  PC
 SG_ Reserved_14 : 20|44@1+ (1,0) [0|17592186044415] ""  PC

BO_ 2334781087 M2P_SUMDATA34__15: 8 MBMU
 SG_ M2P_SOE_Charge_B4 : 0|10@1+ (0.1,0) [0|102.3] "%"  PC
 SG_ M2P_SOE_Discharge_B4 : 10|10@1+ (0.1,0) [0|102.3] "%"  PC
 SG_ Reserved_15 : 20|44@1+ (1,0) [0|17592186044415] ""  PC

BO_ 2334781088 M2P_SUMDATA34__16: 8 MBMU
 SG_ M2P_SOE_Charge_B4 : 0|10@1+ (0.1,0) [0|102.3] "%"  PC
 SG_ M2P_SOE_Discharge_B4 : 10|10@1+ (0.1,0) [0|102.3] "%"  PC
 SG_ Reserved_16 : 20|44@1+ (1,0) [0|17592186044415] ""  PC

BO_ 2334781089 M2P_SUMDATA34__17: 8 MBMU
 SG_ M2P_SOE_Charge_B4 : 0|10@1+ (0.1,0) [0|102.3] "%"  PC
 SG_ M2P_SOE_Discharge_B4 : 10|10@1+ (0.1,0) [0|102.3] "%"  PC
 SG_ Reserved_17 : 20|44@1+ (1,0) [0|17592186044415] ""  PC

BO_ 2334781090 M2P_SUMDATA34__18: 8 MBMU
 SG_ M2P_SOE_Charge_B4 : 0|10@1+ (0.1,0) [0|102.3] "%"  PC
 SG_ M2P_SOE_Discharge_B4 : 10|10@1+ (0.1,0) [0|102.3] "%"  PC
 SG_ Reserved_18 : 20|44@1+ (1,0) [0|17592186044415] ""  PC

BO_ 2334781091 M2P_SUMDATA34__19: 8 MBMU
 SG_ M2P_SOE_Charge_B4 : 0|10@1+ (0.1,0) [0|102.3] "%"  PC
 SG_ M2P_SOE_Discharge_B4 : 10|10@1+ (0.1,0) [0|102.3] "%"  PC
 SG_ Reserved_19 : 20|44@1+ (1,0) [0|17592186044415] ""  PC

BO_ 2334781092 M2P_SUMDATA34__20: 8 MBMU
 SG_ M2P_SOE_Charge_B4 : 0|10@1+ (0.1,0) [0|102.3] "%"  PC
 SG_ M2P_SOE_Discharge_B4 : 10|10@1+ (0.1,0) [0|102.3] "%"  PC
 SG_ Reserved_20 : 20|44@1+ (1,0) [0|17592186044415] ""  PC

BO_ 2334781093 M2P_SUMDATA34__21: 8 MBMU
 SG_ M2P_SOE_Charge_B4 : 0|10@1+ (0.1,0) [0|102.3] "%"  PC
 SG_ M2P_SOE_Discharge_B4 : 10|10@1+ (0.1,0) [0|102.3] "%"  PC
 SG_ Reserved_21 : 20|44@1+ (1,0) [0|17592186044415] ""  PC

BO_ 2334781094 M2P_SUMDATA34__22: 8 MBMU
 SG_ M2P_SOE_Charge_B4 : 0|10@1+ (0.1,0) [0|102.3] "%"  PC
 SG_ M2P_SOE_Discharge_B4 : 10|10@1+ (0.1,0) [0|102.3] "%"  PC
 SG_ Reserved_22 : 20|44@1+ (1,0) [0|17592186044415] ""  PC

BO_ 2334781095 M2P_SUMDATA34__23: 8 MBMU
 SG_ M2P_SOE_Charge_B4 : 0|10@1+ (0.1,0) [0|102.3] "%"  PC
 SG_ M2P_SOE_Discharge_B4 : 10|10@1+ (0.1,0) [0|102.3] "%"  PC
 SG_ Reserved_23 : 20|44@1+ (1,0) [0|17592186044415] ""  PC

BO_ 2334781096 M2P_SUMDATA34__24: 8 MBMU
 SG_ M2P_SOE_Charge_B4 : 0|10@1+ (0.1,0) [0|102.3] "%"  PC
 SG_ M2P_SOE_Discharge_B4 : 10|10@1+ (0.1,0) [0|102.3] "%"  PC
 SG_ Reserved_24 : 20|44@1+ (1,0) [0|17592186044415] ""  PC

BO_ 2334781097 M2P_SUMDATA34__25: 8 MBMU
 SG_ M2P_SOE_Charge_B4 : 0|10@1+ (0.1,0) [0|102.3] "%"  PC
 SG_ M2P_SOE_Discharge_B4 : 10|10@1+ (0.1,0) [0|102.3] "%"  PC
 SG_ Reserved_25 : 20|44@1+ (1,0) [0|17592186044415] ""  PC

BO_ 2334781098 M2P_SUMDATA34__26: 8 MBMU
 SG_ M2P_SOE_Charge_B4 : 0|10@1+ (0.1,0) [0|102.3] "%"  PC
 SG_ M2P_SOE_Discharge_B4 : 10|10@1+ (0.1,0) [0|102.3] "%"  PC
 SG_ Reserved_26 : 20|44@1+ (1,0) [0|17592186044415] ""  PC

BO_ 2334781099 M2P_SUMDATA34__27: 8 MBMU
 SG_ M2P_SOE_Charge_B4 : 0|10@1+ (0.1,0) [0|102.3] "%"  PC
 SG_ M2P_SOE_Discharge_B4 : 10|10@1+ (0.1,0) [0|102.3] "%"  PC
 SG_ Reserved_27 : 20|44@1+ (1,0) [0|17592186044415] ""  PC

BO_ 2334781100 M2P_SUMDATA34__28: 8 MBMU
 SG_ M2P_SOE_Charge_B4 : 0|10@1+ (0.1,0) [0|102.3] "%"  PC
 SG_ M2P_SOE_Discharge_B4 : 10|10@1+ (0.1,0) [0|102.3] "%"  PC
 SG_ Reserved_28 : 20|44@1+ (1,0) [0|17592186044415] ""  PC

BO_ 2334781101 M2P_SUMDATA34__29: 8 MBMU
 SG_ M2P_SOE_Charge_B4 : 0|10@1+ (0.1,0) [0|102.3] "%"  PC
 SG_ M2P_SOE_Discharge_B4 : 10|10@1+ (0.1,0) [0|102.3] "%"  PC
 SG_ Reserved_29 : 20|44@1+ (1,0) [0|17592186044415] ""  PC

BO_ 2334781102 M2P_SUMDATA34__30: 8 MBMU
 SG_ M2P_SOE_Charge_B4 : 0|10@1+ (0.1,0) [0|102.3] "%"  PC
 SG_ M2P_SOE_Discharge_B4 : 10|10@1+ (0.1,0) [0|102.3] "%"  PC
 SG_ Reserved_30 : 20|44@1+ (1,0) [0|17592186044415] ""  PC

BO_ 2334781103 M2P_SUMDATA34__31: 8 MBMU
 SG_ M2P_SOE_Charge_B4 : 0|10@1+ (0.1,0) [0|102.3] "%"  PC
 SG_ M2P_SOE_Discharge_B4 : 10|10@1+ (0.1,0) [0|102.3] "%"  PC
 SG_ Reserved_31 : 20|44@1+ (1,0) [0|17592186044415] ""  PC

BO_ 2334846609 M2P_SUMDATA35__01: 8 MBMU
 SG_ M2P_Measure_Vol_B5_01 : 0|16@1+ (0.1,0) [0|6553.5] "V"  PC,SBMU
 SG_ M2P_Current_B5_01 : 16|16@1+ (1,-20000) [-20000|45535] "A"  PC,SBMU
 SG_ M2P_PermitMaxCharge_I_B5_01 : 32|16@1+ (1,-20000) [-20000|45535] "A"  PC
 SG_ M2P_PermitMaxDisCharge_I_B5_01 : 48|16@1+ (1,-20000) [-20000|45535] "A"  PC

BO_ 2334846610 M2P_SUMDATA35__02: 8 MBMU
 SG_ M2P_Measure_Vol_B5_02 : 0|16@1+ (0.1,0) [0|6553.5] "V"  PC,SBMU
 SG_ M2P_Current_B5_02 : 16|16@1+ (1,-20000) [-20000|45535] "A"  PC,SBMU
 SG_ M2P_PermitMaxCharge_I_B5_02 : 32|16@1+ (1,-20000) [-20000|45535] "A"  PC
 SG_ M2P_PermitMaxDisCharge_I_B5_02 : 48|16@1+ (1,-20000) [-20000|45535] "A"  PC

BO_ 2334846611 M2P_SUMDATA35__03: 8 MBMU
 SG_ M2P_Measure_Vol_B5_03 : 0|16@1+ (0.1,0) [0|6553.5] "V"  PC,SBMU
 SG_ M2P_Current_B5_03 : 16|16@1+ (1,-20000) [-20000|45535] "A"  PC,SBMU
 SG_ M2P_PermitMaxCharge_I_B5_03 : 32|16@1+ (1,-20000) [-20000|45535] "A"  PC
 SG_ M2P_PermitMaxDisCharge_I_B5_03 : 48|16@1+ (1,-20000) [-20000|45535] "A"  PC

BO_ 2334846612 M2P_SUMDATA35__04: 8 MBMU
 SG_ M2P_Measure_Vol_B5_04 : 0|16@1+ (0.1,0) [0|6553.5] "V"  PC,SBMU
 SG_ M2P_Current_B5_04 : 16|16@1+ (1,-20000) [-20000|45535] "A"  PC,SBMU
 SG_ M2P_PermitMaxCharge_I_B5_04 : 32|16@1+ (1,-20000) [-20000|45535] "A"  PC
 SG_ M2P_PermitMaxDisCharge_I_B5_04 : 48|16@1+ (1,-20000) [-20000|45535] "A"  PC

BO_ 2334846613 M2P_SUMDATA35__05: 8 MBMU
 SG_ M2P_Measure_Vol_B5_05 : 0|16@1+ (0.1,0) [0|6553.5] "V"  PC,SBMU
 SG_ M2P_Current_B5_05 : 16|16@1+ (1,-20000) [-20000|45535] "A"  PC,SBMU
 SG_ M2P_PermitMaxCharge_I_B5_05 : 32|16@1+ (1,-20000) [-20000|45535] "A"  PC
 SG_ M2P_PermitMaxDisCharge_I_B5_05 : 48|16@1+ (1,-20000) [-20000|45535] "A"  PC

BO_ 2334846614 M2P_SUMDATA35__06: 8 MBMU
 SG_ M2P_Measure_Vol_B5_06 : 0|16@1+ (0.1,0) [0|6553.5] "V"  PC,SBMU
 SG_ M2P_Current_B5_06 : 16|16@1+ (1,-20000) [-20000|45535] "A"  PC,SBMU
 SG_ M2P_PermitMaxCharge_I_B5_06 : 32|16@1+ (1,-20000) [-20000|45535] "A"  PC
 SG_ M2P_PermitMaxDisCharge_I_B5_06 : 48|16@1+ (1,-20000) [-20000|45535] "A"  PC

BO_ 2334846615 M2P_SUMDATA35__07: 8 MBMU
 SG_ M2P_Measure_Vol_B5_07 : 0|16@1+ (0.1,0) [0|6553.5] "V"  PC,SBMU
 SG_ M2P_Current_B5_07 : 16|16@1+ (1,-20000) [-20000|45535] "A"  PC,SBMU
 SG_ M2P_PermitMaxCharge_I_B5_07 : 32|16@1+ (1,-20000) [-20000|45535] "A"  PC
 SG_ M2P_PermitMaxDisCharge_I_B5_07 : 48|16@1+ (1,-20000) [-20000|45535] "A"  PC

BO_ 2334846616 M2P_SUMDATA35__08: 8 MBMU
 SG_ M2P_Measure_Vol_B5_08 : 0|16@1+ (0.1,0) [0|6553.5] "V"  PC,SBMU
 SG_ M2P_Current_B5_08 : 16|16@1+ (1,-20000) [-20000|45535] "A"  PC,SBMU
 SG_ M2P_PermitMaxCharge_I_B5_08 : 32|16@1+ (1,-20000) [-20000|45535] "A"  PC
 SG_ M2P_PermitMaxDisCharge_I_B5_08 : 48|16@1+ (1,-20000) [-20000|45535] "A"  PC

BO_ 2334846617 M2P_SUMDATA35__09: 8 MBMU
 SG_ M2P_Measure_Vol_B5_09 : 0|16@1+ (0.1,0) [0|6553.5] "V"  PC,SBMU
 SG_ M2P_Current_B5_09 : 16|16@1+ (1,-20000) [-20000|45535] "A"  PC,SBMU
 SG_ M2P_PermitMaxCharge_I_B5_09 : 32|16@1+ (1,-20000) [-20000|45535] "A"  PC
 SG_ M2P_PermitMaxDisCharge_I_B5_09 : 48|16@1+ (1,-20000) [-20000|45535] "A"  PC

BO_ 2334846618 M2P_SUMDATA35__10: 8 MBMU
 SG_ M2P_Measure_Vol_B5_10 : 0|16@1+ (0.1,0) [0|6553.5] "V"  PC,SBMU
 SG_ M2P_Current_B5_10 : 16|16@1+ (1,-20000) [-20000|45535] "A"  PC,SBMU
 SG_ M2P_PermitMaxCharge_I_B5_10 : 32|16@1+ (1,-20000) [-20000|45535] "A"  PC
 SG_ M2P_PermitMaxDisCharge_I_B5_10 : 48|16@1+ (1,-20000) [-20000|45535] "A"  PC

BO_ 2334846619 M2P_SUMDATA35__11: 8 MBMU
 SG_ M2P_Measure_Vol_B5_11 : 0|16@1+ (0.1,0) [0|6553.5] "V"  PC,SBMU
 SG_ M2P_Current_B5_11 : 16|16@1+ (1,-20000) [-20000|45535] "A"  PC,SBMU
 SG_ M2P_PermitMaxCharge_I_B5_11 : 32|16@1+ (1,-20000) [-20000|45535] "A"  PC
 SG_ M2P_PermitMaxDisCharge_I_B5_11 : 48|16@1+ (1,-20000) [-20000|45535] "A"  PC

BO_ 2334846620 M2P_SUMDATA35__12: 8 MBMU
 SG_ M2P_Measure_Vol_B5_12 : 0|16@1+ (0.1,0) [0|6553.5] "V"  PC,SBMU
 SG_ M2P_Current_B5_12 : 16|16@1+ (1,-20000) [-20000|45535] "A"  PC,SBMU
 SG_ M2P_PermitMaxCharge_I_B5_12 : 32|16@1+ (1,-20000) [-20000|45535] "A"  PC
 SG_ M2P_PermitMaxDisCharge_I_B5_12 : 48|16@1+ (1,-20000) [-20000|45535] "A"  PC

BO_ 2334846621 M2P_SUMDATA35__13: 8 MBMU
 SG_ M2P_Measure_Vol_B5_13 : 0|16@1+ (0.1,0) [0|6553.5] "V"  PC,SBMU
 SG_ M2P_Current_B5_13 : 16|16@1+ (1,-20000) [-20000|45535] "A"  PC,SBMU
 SG_ M2P_PermitMaxCharge_I_B5_13 : 32|16@1+ (1,-20000) [-20000|45535] "A"  PC
 SG_ M2P_PermitMaxDisCharge_I_B5_13 : 48|16@1+ (1,-20000) [-20000|45535] "A"  PC

BO_ 2334846622 M2P_SUMDATA35__14: 8 MBMU
 SG_ M2P_Measure_Vol_B5_14 : 0|16@1+ (0.1,0) [0|6553.5] "V"  PC,SBMU
 SG_ M2P_Current_B5_14 : 16|16@1+ (1,-20000) [-20000|45535] "A"  PC,SBMU
 SG_ M2P_PermitMaxCharge_I_B5_14 : 32|16@1+ (1,-20000) [-20000|45535] "A"  PC
 SG_ M2P_PermitMaxDisCharge_I_B5_14 : 48|16@1+ (1,-20000) [-20000|45535] "A"  PC

BO_ 2334846623 M2P_SUMDATA35__15: 8 MBMU
 SG_ M2P_Measure_Vol_B5_15 : 0|16@1+ (0.1,0) [0|6553.5] "V"  PC,SBMU
 SG_ M2P_Current_B5_15 : 16|16@1+ (1,-20000) [-20000|45535] "A"  PC,SBMU
 SG_ M2P_PermitMaxCharge_I_B5_15 : 32|16@1+ (1,-20000) [-20000|45535] "A"  PC
 SG_ M2P_PermitMaxDisCharge_I_B5_15 : 48|16@1+ (1,-20000) [-20000|45535] "A"  PC

BO_ 2334846624 M2P_SUMDATA35__16: 8 MBMU
 SG_ M2P_Measure_Vol_B5_16 : 0|16@1+ (0.1,0) [0|6553.5] "V"  PC,SBMU
 SG_ M2P_Current_B5_16 : 16|16@1+ (1,-20000) [-20000|45535] "A"  PC,SBMU
 SG_ M2P_PermitMaxCharge_I_B5_16 : 32|16@1+ (1,-20000) [-20000|45535] "A"  PC
 SG_ M2P_PermitMaxDisCharge_I_B5_16 : 48|16@1+ (1,-20000) [-20000|45535] "A"  PC

BO_ 2334846625 M2P_SUMDATA35__17: 8 MBMU
 SG_ M2P_Measure_Vol_B5_17 : 0|16@1+ (0.1,0) [0|6553.5] "V"  PC,SBMU
 SG_ M2P_Current_B5_17 : 16|16@1+ (1,-20000) [-20000|45535] "A"  PC,SBMU
 SG_ M2P_PermitMaxCharge_I_B5_17 : 32|16@1+ (1,-20000) [-20000|45535] "A"  PC
 SG_ M2P_PermitMaxDisCharge_I_B5_17 : 48|16@1+ (1,-20000) [-20000|45535] "A"  PC

BO_ 2334846626 M2P_SUMDATA35__18: 8 MBMU
 SG_ M2P_Measure_Vol_B5_18 : 0|16@1+ (0.1,0) [0|6553.5] "V"  PC,SBMU
 SG_ M2P_Current_B5_18 : 16|16@1+ (1,-20000) [-20000|45535] "A"  PC,SBMU
 SG_ M2P_PermitMaxCharge_I_B5_18 : 32|16@1+ (1,-20000) [-20000|45535] "A"  PC
 SG_ M2P_PermitMaxDisCharge_I_B5_18 : 48|16@1+ (1,-20000) [-20000|45535] "A"  PC

BO_ 2334846627 M2P_SUMDATA35__19: 8 MBMU
 SG_ M2P_Measure_Vol_B5_19 : 0|16@1+ (0.1,0) [0|6553.5] "V"  PC,SBMU
 SG_ M2P_Current_B5_19 : 16|16@1+ (1,-20000) [-20000|45535] "A"  PC,SBMU
 SG_ M2P_PermitMaxCharge_I_B5_19 : 32|16@1+ (1,-20000) [-20000|45535] "A"  PC
 SG_ M2P_PermitMaxDisCharge_I_B5_19 : 48|16@1+ (1,-20000) [-20000|45535] "A"  PC

BO_ 2334846628 M2P_SUMDATA35__20: 8 MBMU
 SG_ M2P_Measure_Vol_B5_20 : 0|16@1+ (0.1,0) [0|6553.5] "V"  PC,SBMU
 SG_ M2P_Current_B5_20 : 16|16@1+ (1,-20000) [-20000|45535] "A"  PC,SBMU
 SG_ M2P_PermitMaxCharge_I_B5_20 : 32|16@1+ (1,-20000) [-20000|45535] "A"  PC
 SG_ M2P_PermitMaxDisCharge_I_B5_20 : 48|16@1+ (1,-20000) [-20000|45535] "A"  PC

BO_ 2334846629 M2P_SUMDATA35__21: 8 MBMU
 SG_ M2P_Measure_Vol_B5_21 : 0|16@1+ (0.1,0) [0|6553.5] "V"  PC,SBMU
 SG_ M2P_Current_B5_21 : 16|16@1+ (1,-20000) [-20000|45535] "A"  PC,SBMU
 SG_ M2P_PermitMaxCharge_I_B5_21 : 32|16@1+ (1,-20000) [-20000|45535] "A"  PC
 SG_ M2P_PermitMaxDisCharge_I_B5_21 : 48|16@1+ (1,-20000) [-20000|45535] "A"  PC

BO_ 2334846630 M2P_SUMDATA35__22: 8 MBMU
 SG_ M2P_Measure_Vol_B5_22 : 0|16@1+ (0.1,0) [0|6553.5] "V"  PC,SBMU
 SG_ M2P_Current_B5_22 : 16|16@1+ (1,-20000) [-20000|45535] "A"  PC,SBMU
 SG_ M2P_PermitMaxCharge_I_B5_22 : 32|16@1+ (1,-20000) [-20000|45535] "A"  PC
 SG_ M2P_PermitMaxDisCharge_I_B5_22 : 48|16@1+ (1,-20000) [-20000|45535] "A"  PC

BO_ 2334846631 M2P_SUMDATA35__23: 8 MBMU
 SG_ M2P_Measure_Vol_B5_23 : 0|16@1+ (0.1,0) [0|6553.5] "V"  PC,SBMU
 SG_ M2P_Current_B5_23 : 16|16@1+ (1,-20000) [-20000|45535] "A"  PC,SBMU
 SG_ M2P_PermitMaxCharge_I_B5_23 : 32|16@1+ (1,-20000) [-20000|45535] "A"  PC
 SG_ M2P_PermitMaxDisCharge_I_B5_23 : 48|16@1+ (1,-20000) [-20000|45535] "A"  PC

BO_ 2334846632 M2P_SUMDATA35__24: 8 MBMU
 SG_ M2P_Measure_Vol_B5_24 : 0|16@1+ (0.1,0) [0|6553.5] "V"  PC,SBMU
 SG_ M2P_Current_B5_24 : 16|16@1+ (1,-20000) [-20000|45535] "A"  PC,SBMU
 SG_ M2P_PermitMaxCharge_I_B5_24 : 32|16@1+ (1,-20000) [-20000|45535] "A"  PC
 SG_ M2P_PermitMaxDisCharge_I_B5_24 : 48|16@1+ (1,-20000) [-20000|45535] "A"  PC

BO_ 2334846633 M2P_SUMDATA35__25: 8 MBMU
 SG_ M2P_Measure_Vol_B5_25 : 0|16@1+ (0.1,0) [0|6553.5] "V"  PC,SBMU
 SG_ M2P_Current_B5_25 : 16|16@1+ (1,-20000) [-20000|45535] "A"  PC,SBMU
 SG_ M2P_PermitMaxCharge_I_B5_25 : 32|16@1+ (1,-20000) [-20000|45535] "A"  PC
 SG_ M2P_PermitMaxDisCharge_I_B5_25 : 48|16@1+ (1,-20000) [-20000|45535] "A"  PC

BO_ 2334846634 M2P_SUMDATA35__26: 8 MBMU
 SG_ M2P_Measure_Vol_B5_26 : 0|16@1+ (0.1,0) [0|6553.5] "V"  PC,SBMU
 SG_ M2P_Current_B5_26 : 16|16@1+ (1,-20000) [-20000|45535] "A"  PC,SBMU
 SG_ M2P_PermitMaxCharge_I_B5_26 : 32|16@1+ (1,-20000) [-20000|45535] "A"  PC
 SG_ M2P_PermitMaxDisCharge_I_B5_26 : 48|16@1+ (1,-20000) [-20000|45535] "A"  PC

BO_ 2334846635 M2P_SUMDATA35__27: 8 MBMU
 SG_ M2P_Measure_Vol_B5_27 : 0|16@1+ (0.1,0) [0|6553.5] "V"  PC,SBMU
 SG_ M2P_Current_B5_27 : 16|16@1+ (1,-20000) [-20000|45535] "A"  PC,SBMU
 SG_ M2P_PermitMaxCharge_I_B5_27 : 32|16@1+ (1,-20000) [-20000|45535] "A"  PC
 SG_ M2P_PermitMaxDisCharge_I_B5_27 : 48|16@1+ (1,-20000) [-20000|45535] "A"  PC

BO_ 2334846636 M2P_SUMDATA35__28: 8 MBMU
 SG_ M2P_Measure_Vol_B5_28 : 0|16@1+ (0.1,0) [0|6553.5] "V"  PC,SBMU
 SG_ M2P_Current_B5_28 : 16|16@1+ (1,-20000) [-20000|45535] "A"  PC,SBMU
 SG_ M2P_PermitMaxCharge_I_B5_28 : 32|16@1+ (1,-20000) [-20000|45535] "A"  PC
 SG_ M2P_PermitMaxDisCharge_I_B5_28 : 48|16@1+ (1,-20000) [-20000|45535] "A"  PC

BO_ 2334846637 M2P_SUMDATA35__29: 8 MBMU
 SG_ M2P_Measure_Vol_B5_29 : 0|16@1+ (0.1,0) [0|6553.5] "V"  PC,SBMU
 SG_ M2P_Current_B5_29 : 16|16@1+ (1,-20000) [-20000|45535] "A"  PC,SBMU
 SG_ M2P_PermitMaxCharge_I_B5_29 : 32|16@1+ (1,-20000) [-20000|45535] "A"  PC
 SG_ M2P_PermitMaxDisCharge_I_B5_29 : 48|16@1+ (1,-20000) [-20000|45535] "A"  PC

BO_ 2334846638 M2P_SUMDATA35__30: 8 MBMU
 SG_ M2P_Measure_Vol_B5_30 : 0|16@1+ (0.1,0) [0|6553.5] "V"  PC,SBMU
 SG_ M2P_Current_B5_30 : 16|16@1+ (1,-20000) [-20000|45535] "A"  PC,SBMU
 SG_ M2P_PermitMaxCharge_I_B5_30 : 32|16@1+ (1,-20000) [-20000|45535] "A"  PC
 SG_ M2P_PermitMaxDisCharge_I_B5_30 : 48|16@1+ (1,-20000) [-20000|45535] "A"  PC

BO_ 2334846639 M2P_SUMDATA35__31: 8 MBMU
 SG_ M2P_Measure_Vol_B5_31 : 0|16@1+ (0.1,0) [0|6553.5] "V"  PC,SBMU
 SG_ M2P_Current_B5_31 : 16|16@1+ (1,-20000) [-20000|45535] "A"  PC,SBMU
 SG_ M2P_PermitMaxCharge_I_B5_31 : 32|16@1+ (1,-20000) [-20000|45535] "A"  PC
 SG_ M2P_PermitMaxDisCharge_I_B5_31 : 48|16@1+ (1,-20000) [-20000|45535] "A"  PC

BO_ 2334912145 M2P_SUMDATA36__01: 8 MBMU
 SG_ M2P_PermitMaxVolt_B5_01 : 0|16@1+ (0.1,0) [0|6553.5] "V"  PC
 SG_ M2P_PermitMinVolt_B5_01 : 16|16@1+ (0.1,0) [0|6553.5] "V"  PC
 SG_ M2P_PermitMaxPow_Chg_B5_01 : 32|16@1+ (1,-20000) [-20000|45535] "Kw"  PC
 SG_ M2P_PermitMaxPow_DisChg_B5_01 : 48|16@1+ (1,-20000) [-20000|45535] "Kw"  PC

BO_ 2334912146 M2P_SUMDATA36__02: 8 MBMU
 SG_ M2P_PermitMaxVolt_B5_02 : 0|16@1+ (0.1,0) [0|6553.5] "V"  PC
 SG_ M2P_PermitMinVolt_B5_02 : 16|16@1+ (0.1,0) [0|6553.5] "V"  PC
 SG_ M2P_PermitMaxPow_Chg_B5_02 : 32|16@1+ (1,-20000) [-20000|45535] "Kw"  PC
 SG_ M2P_PermitMaxPow_DisChg_B5_02 : 48|16@1+ (1,-20000) [-20000|45535] "Kw"  PC

BO_ 2334912147 M2P_SUMDATA36__03: 8 MBMU
 SG_ M2P_PermitMaxVolt_B5_03 : 0|16@1+ (0.1,0) [0|6553.5] "V"  PC
 SG_ M2P_PermitMinVolt_B5_03 : 16|16@1+ (0.1,0) [0|6553.5] "V"  PC
 SG_ M2P_PermitMaxPow_Chg_B5_03 : 32|16@1+ (1,-20000) [-20000|45535] "Kw"  PC
 SG_ M2P_PermitMaxPow_DisChg_B5_03 : 48|16@1+ (1,-20000) [-20000|45535] "Kw"  PC

BO_ 2334912148 M2P_SUMDATA36__04: 8 MBMU
 SG_ M2P_PermitMaxVolt_B5_04 : 0|16@1+ (0.1,0) [0|6553.5] "V"  PC
 SG_ M2P_PermitMinVolt_B5_04 : 16|16@1+ (0.1,0) [0|6553.5] "V"  PC
 SG_ M2P_PermitMaxPow_Chg_B5_04 : 32|16@1+ (1,-20000) [-20000|45535] "Kw"  PC
 SG_ M2P_PermitMaxPow_DisChg_B5_04 : 48|16@1+ (1,-20000) [-20000|45535] "Kw"  PC

BO_ 2334912149 M2P_SUMDATA36__05: 8 MBMU
 SG_ M2P_PermitMaxVolt_B5_05 : 0|16@1+ (0.1,0) [0|6553.5] "V"  PC
 SG_ M2P_PermitMinVolt_B5_05 : 16|16@1+ (0.1,0) [0|6553.5] "V"  PC
 SG_ M2P_PermitMaxPow_Chg_B5_05 : 32|16@1+ (1,-20000) [-20000|45535] "Kw"  PC
 SG_ M2P_PermitMaxPow_DisChg_B5_05 : 48|16@1+ (1,-20000) [-20000|45535] "Kw"  PC

BO_ 2334912150 M2P_SUMDATA36__06: 8 MBMU
 SG_ M2P_PermitMaxVolt_B5_06 : 0|16@1+ (0.1,0) [0|6553.5] "V"  PC
 SG_ M2P_PermitMinVolt_B5_06 : 16|16@1+ (0.1,0) [0|6553.5] "V"  PC
 SG_ M2P_PermitMaxPow_Chg_B5_06 : 32|16@1+ (1,-20000) [-20000|45535] "Kw"  PC
 SG_ M2P_PermitMaxPow_DisChg_B5_06 : 48|16@1+ (1,-20000) [-20000|45535] "Kw"  PC

BO_ 2334912151 M2P_SUMDATA36__07: 8 MBMU
 SG_ M2P_PermitMaxVolt_B5_07 : 0|16@1+ (0.1,0) [0|6553.5] "V"  PC
 SG_ M2P_PermitMinVolt_B5_07 : 16|16@1+ (0.1,0) [0|6553.5] "V"  PC
 SG_ M2P_PermitMaxPow_Chg_B5_07 : 32|16@1+ (1,-20000) [-20000|45535] "Kw"  PC
 SG_ M2P_PermitMaxPow_DisChg_B5_07 : 48|16@1+ (1,-20000) [-20000|45535] "Kw"  PC

BO_ 2334912152 M2P_SUMDATA36__08: 8 MBMU
 SG_ M2P_PermitMaxVolt_B5_08 : 0|16@1+ (0.1,0) [0|6553.5] "V"  PC
 SG_ M2P_PermitMinVolt_B5_08 : 16|16@1+ (0.1,0) [0|6553.5] "V"  PC
 SG_ M2P_PermitMaxPow_Chg_B5_08 : 32|16@1+ (1,-20000) [-20000|45535] "Kw"  PC
 SG_ M2P_PermitMaxPow_DisChg_B5_08 : 48|16@1+ (1,-20000) [-20000|45535] "Kw"  PC

BO_ 2334912153 M2P_SUMDATA36__09: 8 MBMU
 SG_ M2P_PermitMaxVolt_B5_09 : 0|16@1+ (0.1,0) [0|6553.5] "V"  PC
 SG_ M2P_PermitMinVolt_B5_09 : 16|16@1+ (0.1,0) [0|6553.5] "V"  PC
 SG_ M2P_PermitMaxPow_Chg_B5_09 : 32|16@1+ (1,-20000) [-20000|45535] "Kw"  PC
 SG_ M2P_PermitMaxPow_DisChg_B5_09 : 48|16@1+ (1,-20000) [-20000|45535] "Kw"  PC

BO_ 2334912154 M2P_SUMDATA36__10: 8 MBMU
 SG_ M2P_PermitMaxVolt_B5_10 : 0|16@1+ (0.1,0) [0|6553.5] "V"  PC
 SG_ M2P_PermitMinVolt_B5_10 : 16|16@1+ (0.1,0) [0|6553.5] "V"  PC
 SG_ M2P_PermitMaxPow_Chg_B5_10 : 32|16@1+ (1,-20000) [-20000|45535] "Kw"  PC
 SG_ M2P_PermitMaxPow_DisChg_B5_10 : 48|16@1+ (1,-20000) [-20000|45535] "Kw"  PC

BO_ 2334912155 M2P_SUMDATA36__11: 8 MBMU
 SG_ M2P_PermitMaxVolt_B5_11 : 0|16@1+ (0.1,0) [0|6553.5] "V"  PC
 SG_ M2P_PermitMinVolt_B5_11 : 16|16@1+ (0.1,0) [0|6553.5] "V"  PC
 SG_ M2P_PermitMaxPow_Chg_B5_11 : 32|16@1+ (1,-20000) [-20000|45535] "Kw"  PC
 SG_ M2P_PermitMaxPow_DisChg_B5_11 : 48|16@1+ (1,-20000) [-20000|45535] "Kw"  PC

BO_ 2334912156 M2P_SUMDATA36__12: 8 MBMU
 SG_ M2P_PermitMaxVolt_B5_12 : 0|16@1+ (0.1,0) [0|6553.5] "V"  PC
 SG_ M2P_PermitMinVolt_B5_12 : 16|16@1+ (0.1,0) [0|6553.5] "V"  PC
 SG_ M2P_PermitMaxPow_Chg_B5_12 : 32|16@1+ (1,-20000) [-20000|45535] "Kw"  PC
 SG_ M2P_PermitMaxPow_DisChg_B5_12 : 48|16@1+ (1,-20000) [-20000|45535] "Kw"  PC

BO_ 2334912157 M2P_SUMDATA36__13: 8 MBMU
 SG_ M2P_PermitMaxVolt_B5_13 : 0|16@1+ (0.1,0) [0|6553.5] "V"  PC
 SG_ M2P_PermitMinVolt_B5_13 : 16|16@1+ (0.1,0) [0|6553.5] "V"  PC
 SG_ M2P_PermitMaxPow_Chg_B5_13 : 32|16@1+ (1,-20000) [-20000|45535] "Kw"  PC
 SG_ M2P_PermitMaxPow_DisChg_B5_13 : 48|16@1+ (1,-20000) [-20000|45535] "Kw"  PC

BO_ 2334912158 M2P_SUMDATA36__14: 8 MBMU
 SG_ M2P_PermitMaxVolt_B5_14 : 0|16@1+ (0.1,0) [0|6553.5] "V"  PC
 SG_ M2P_PermitMinVolt_B5_14 : 16|16@1+ (0.1,0) [0|6553.5] "V"  PC
 SG_ M2P_PermitMaxPow_Chg_B5_14 : 32|16@1+ (1,-20000) [-20000|45535] "Kw"  PC
 SG_ M2P_PermitMaxPow_DisChg_B5_14 : 48|16@1+ (1,-20000) [-20000|45535] "Kw"  PC

BO_ 2334912159 M2P_SUMDATA36__15: 8 MBMU
 SG_ M2P_PermitMaxVolt_B5_15 : 0|16@1+ (0.1,0) [0|6553.5] "V"  PC
 SG_ M2P_PermitMinVolt_B5_15 : 16|16@1+ (0.1,0) [0|6553.5] "V"  PC
 SG_ M2P_PermitMaxPow_Chg_B5_15 : 32|16@1+ (1,-20000) [-20000|45535] "Kw"  PC
 SG_ M2P_PermitMaxPow_DisChg_B5_15 : 48|16@1+ (1,-20000) [-20000|45535] "Kw"  PC

BO_ 2334912160 M2P_SUMDATA36__16: 8 MBMU
 SG_ M2P_PermitMaxVolt_B5_16 : 0|16@1+ (0.1,0) [0|6553.5] "V"  PC
 SG_ M2P_PermitMinVolt_B5_16 : 16|16@1+ (0.1,0) [0|6553.5] "V"  PC
 SG_ M2P_PermitMaxPow_Chg_B5_16 : 32|16@1+ (1,-20000) [-20000|45535] "Kw"  PC
 SG_ M2P_PermitMaxPow_DisChg_B5_16 : 48|16@1+ (1,-20000) [-20000|45535] "Kw"  PC

BO_ 2334912161 M2P_SUMDATA36__17: 8 MBMU
 SG_ M2P_PermitMaxVolt_B5_17 : 0|16@1+ (0.1,0) [0|6553.5] "V"  PC
 SG_ M2P_PermitMinVolt_B5_17 : 16|16@1+ (0.1,0) [0|6553.5] "V"  PC
 SG_ M2P_PermitMaxPow_Chg_B5_17 : 32|16@1+ (1,-20000) [-20000|45535] "Kw"  PC
 SG_ M2P_PermitMaxPow_DisChg_B5_17 : 48|16@1+ (1,-20000) [-20000|45535] "Kw"  PC

BO_ 2334912162 M2P_SUMDATA36__18: 8 MBMU
 SG_ M2P_PermitMaxVolt_B5_18 : 0|16@1+ (0.1,0) [0|6553.5] "V"  PC
 SG_ M2P_PermitMinVolt_B5_18 : 16|16@1+ (0.1,0) [0|6553.5] "V"  PC
 SG_ M2P_PermitMaxPow_Chg_B5_18 : 32|16@1+ (1,-20000) [-20000|45535] "Kw"  PC
 SG_ M2P_PermitMaxPow_DisChg_B5_18 : 48|16@1+ (1,-20000) [-20000|45535] "Kw"  PC

BO_ 2334912163 M2P_SUMDATA36__19: 8 MBMU
 SG_ M2P_PermitMaxVolt_B5_19 : 0|16@1+ (0.1,0) [0|6553.5] "V"  PC
 SG_ M2P_PermitMinVolt_B5_19 : 16|16@1+ (0.1,0) [0|6553.5] "V"  PC
 SG_ M2P_PermitMaxPow_Chg_B5_19 : 32|16@1+ (1,-20000) [-20000|45535] "Kw"  PC
 SG_ M2P_PermitMaxPow_DisChg_B5_19 : 48|16@1+ (1,-20000) [-20000|45535] "Kw"  PC

BO_ 2334912164 M2P_SUMDATA36__20: 8 MBMU
 SG_ M2P_PermitMaxVolt_B5_20 : 0|16@1+ (0.1,0) [0|6553.5] "V"  PC
 SG_ M2P_PermitMinVolt_B5_20 : 16|16@1+ (0.1,0) [0|6553.5] "V"  PC
 SG_ M2P_PermitMaxPow_Chg_B5_20 : 32|16@1+ (1,-20000) [-20000|45535] "Kw"  PC
 SG_ M2P_PermitMaxPow_DisChg_B5_20 : 48|16@1+ (1,-20000) [-20000|45535] "Kw"  PC

BO_ 2334912165 M2P_SUMDATA36__21: 8 MBMU
 SG_ M2P_PermitMaxVolt_B5_21 : 0|16@1+ (0.1,0) [0|6553.5] "V"  PC
 SG_ M2P_PermitMinVolt_B5_21 : 16|16@1+ (0.1,0) [0|6553.5] "V"  PC
 SG_ M2P_PermitMaxPow_Chg_B5_21 : 32|16@1+ (1,-20000) [-20000|45535] "Kw"  PC
 SG_ M2P_PermitMaxPow_DisChg_B5_21 : 48|16@1+ (1,-20000) [-20000|45535] "Kw"  PC

BO_ 2334912166 M2P_SUMDATA36__22: 8 MBMU
 SG_ M2P_PermitMaxVolt_B5_22 : 0|16@1+ (0.1,0) [0|6553.5] "V"  PC
 SG_ M2P_PermitMinVolt_B5_22 : 16|16@1+ (0.1,0) [0|6553.5] "V"  PC
 SG_ M2P_PermitMaxPow_Chg_B5_22 : 32|16@1+ (1,-20000) [-20000|45535] "Kw"  PC
 SG_ M2P_PermitMaxPow_DisChg_B5_22 : 48|16@1+ (1,-20000) [-20000|45535] "Kw"  PC

BO_ 2334912167 M2P_SUMDATA36__23: 8 MBMU
 SG_ M2P_PermitMaxVolt_B5_23 : 0|16@1+ (0.1,0) [0|6553.5] "V"  PC
 SG_ M2P_PermitMinVolt_B5_23 : 16|16@1+ (0.1,0) [0|6553.5] "V"  PC
 SG_ M2P_PermitMaxPow_Chg_B5_23 : 32|16@1+ (1,-20000) [-20000|45535] "Kw"  PC
 SG_ M2P_PermitMaxPow_DisChg_B5_23 : 48|16@1+ (1,-20000) [-20000|45535] "Kw"  PC

BO_ 2334912168 M2P_SUMDATA36__24: 8 MBMU
 SG_ M2P_PermitMaxVolt_B5_24 : 0|16@1+ (0.1,0) [0|6553.5] "V"  PC
 SG_ M2P_PermitMinVolt_B5_24 : 16|16@1+ (0.1,0) [0|6553.5] "V"  PC
 SG_ M2P_PermitMaxPow_Chg_B5_24 : 32|16@1+ (1,-20000) [-20000|45535] "Kw"  PC
 SG_ M2P_PermitMaxPow_DisChg_B5_24 : 48|16@1+ (1,-20000) [-20000|45535] "Kw"  PC

BO_ 2334912169 M2P_SUMDATA36__25: 8 MBMU
 SG_ M2P_PermitMaxVolt_B5_25 : 0|16@1+ (0.1,0) [0|6553.5] "V"  PC
 SG_ M2P_PermitMinVolt_B5_25 : 16|16@1+ (0.1,0) [0|6553.5] "V"  PC
 SG_ M2P_PermitMaxPow_Chg_B5_25 : 32|16@1+ (1,-20000) [-20000|45535] "Kw"  PC
 SG_ M2P_PermitMaxPow_DisChg_B5_25 : 48|16@1+ (1,-20000) [-20000|45535] "Kw"  PC

BO_ 2334912170 M2P_SUMDATA36__26: 8 MBMU
 SG_ M2P_PermitMaxVolt_B5_26 : 0|16@1+ (0.1,0) [0|6553.5] "V"  PC
 SG_ M2P_PermitMinVolt_B5_26 : 16|16@1+ (0.1,0) [0|6553.5] "V"  PC
 SG_ M2P_PermitMaxPow_Chg_B5_26 : 32|16@1+ (1,-20000) [-20000|45535] "Kw"  PC
 SG_ M2P_PermitMaxPow_DisChg_B5_26 : 48|16@1+ (1,-20000) [-20000|45535] "Kw"  PC

BO_ 2334912171 M2P_SUMDATA36__27: 8 MBMU
 SG_ M2P_PermitMaxVolt_B5_27 : 0|16@1+ (0.1,0) [0|6553.5] "V"  PC
 SG_ M2P_PermitMinVolt_B5_27 : 16|16@1+ (0.1,0) [0|6553.5] "V"  PC
 SG_ M2P_PermitMaxPow_Chg_B5_27 : 32|16@1+ (1,-20000) [-20000|45535] "Kw"  PC
 SG_ M2P_PermitMaxPow_DisChg_B5_27 : 48|16@1+ (1,-20000) [-20000|45535] "Kw"  PC

BO_ 2334912172 M2P_SUMDATA36__28: 8 MBMU
 SG_ M2P_PermitMaxVolt_B5_28 : 0|16@1+ (0.1,0) [0|6553.5] "V"  PC
 SG_ M2P_PermitMinVolt_B5_28 : 16|16@1+ (0.1,0) [0|6553.5] "V"  PC
 SG_ M2P_PermitMaxPow_Chg_B5_28 : 32|16@1+ (1,-20000) [-20000|45535] "Kw"  PC
 SG_ M2P_PermitMaxPow_DisChg_B5_28 : 48|16@1+ (1,-20000) [-20000|45535] "Kw"  PC

BO_ 2334912173 M2P_SUMDATA36__29: 8 MBMU
 SG_ M2P_PermitMaxVolt_B5_29 : 0|16@1+ (0.1,0) [0|6553.5] "V"  PC
 SG_ M2P_PermitMinVolt_B5_29 : 16|16@1+ (0.1,0) [0|6553.5] "V"  PC
 SG_ M2P_PermitMaxPow_Chg_B5_29 : 32|16@1+ (1,-20000) [-20000|45535] "Kw"  PC
 SG_ M2P_PermitMaxPow_DisChg_B5_29 : 48|16@1+ (1,-20000) [-20000|45535] "Kw"  PC

BO_ 2334912174 M2P_SUMDATA36__30: 8 MBMU
 SG_ M2P_PermitMaxVolt_B5_30 : 0|16@1+ (0.1,0) [0|6553.5] "V"  PC
 SG_ M2P_PermitMinVolt_B5_30 : 16|16@1+ (0.1,0) [0|6553.5] "V"  PC
 SG_ M2P_PermitMaxPow_Chg_B5_30 : 32|16@1+ (1,-20000) [-20000|45535] "Kw"  PC
 SG_ M2P_PermitMaxPow_DisChg_B5_30 : 48|16@1+ (1,-20000) [-20000|45535] "Kw"  PC

BO_ 2334912175 M2P_SUMDATA36__31: 8 MBMU
 SG_ M2P_PermitMaxVolt_B5_31 : 0|16@1+ (0.1,0) [0|6553.5] "V"  PC
 SG_ M2P_PermitMinVolt_B5_31 : 16|16@1+ (0.1,0) [0|6553.5] "V"  PC
 SG_ M2P_PermitMaxPow_Chg_B5_31 : 32|16@1+ (1,-20000) [-20000|45535] "Kw"  PC
 SG_ M2P_PermitMaxPow_DisChg_B5_31 : 48|16@1+ (1,-20000) [-20000|45535] "Kw"  PC

BO_ 2334977681 M2P_SUMDATA37__01: 8 MBMU
 SG_ M2P_Power_B5_01 : 0|16@1+ (1,-20000) [-20000|45535] "Kw"  PC
 SG_ M2P_SysremEngy_Chg_B5_01 : 16|16@1+ (1,0) [0|65535] "Kwh"  PC
 SG_ M2P_SysremEngy_DisChg_B5_01 : 32|16@1+ (1,0) [0|65535] "Kwh"  PC
 SG_ M2P_SysMaxVolt_B5_01 : 48|16@1+ (1,0) [0|65535] "mv"  PC

BO_ 2334977682 M2P_SUMDATA37__02: 8 MBMU
 SG_ M2P_Power_B5_02 : 0|16@1+ (1,-20000) [-20000|45535] "Kw"  PC
 SG_ M2P_SysremEngy_Chg_B5_02 : 16|16@1+ (1,0) [0|65535] "Kwh"  PC
 SG_ M2P_SysremEngy_DisChg_B5_02 : 32|16@1+ (1,0) [0|65535] "Kwh"  PC
 SG_ M2P_SysMaxVolt_B5_02 : 48|16@1+ (1,0) [0|65535] "mv"  PC

BO_ 2334977683 M2P_SUMDATA37__03: 8 MBMU
 SG_ M2P_Power_B5_03 : 0|16@1+ (1,-20000) [-20000|45535] "Kw"  PC
 SG_ M2P_SysremEngy_Chg_B5_03 : 16|16@1+ (1,0) [0|65535] "Kwh"  PC
 SG_ M2P_SysremEngy_DisChg_B5_03 : 32|16@1+ (1,0) [0|65535] "Kwh"  PC
 SG_ M2P_SysMaxVolt_B5_03 : 48|16@1+ (1,0) [0|65535] "mv"  PC

BO_ 2334977684 M2P_SUMDATA37__04: 8 MBMU
 SG_ M2P_Power_B5_04 : 0|16@1+ (1,-20000) [-20000|45535] "Kw"  PC
 SG_ M2P_SysremEngy_Chg_B5_04 : 16|16@1+ (1,0) [0|65535] "Kwh"  PC
 SG_ M2P_SysremEngy_DisChg_B5_04 : 32|16@1+ (1,0) [0|65535] "Kwh"  PC
 SG_ M2P_SysMaxVolt_B5_04 : 48|16@1+ (1,0) [0|65535] "mv"  PC

BO_ 2334977685 M2P_SUMDATA37__05: 8 MBMU
 SG_ M2P_Power_B5_05 : 0|16@1+ (1,-20000) [-20000|45535] "Kw"  PC
 SG_ M2P_SysremEngy_Chg_B5_05 : 16|16@1+ (1,0) [0|65535] "Kwh"  PC
 SG_ M2P_SysremEngy_DisChg_B5_05 : 32|16@1+ (1,0) [0|65535] "Kwh"  PC
 SG_ M2P_SysMaxVolt_B5_05 : 48|16@1+ (1,0) [0|65535] "mv"  PC

BO_ 2334977686 M2P_SUMDATA37__06: 8 MBMU
 SG_ M2P_Power_B5_06 : 0|16@1+ (1,-20000) [-20000|45535] "Kw"  PC
 SG_ M2P_SysremEngy_Chg_B5_06 : 16|16@1+ (1,0) [0|65535] "Kwh"  PC
 SG_ M2P_SysremEngy_DisChg_B5_06 : 32|16@1+ (1,0) [0|65535] "Kwh"  PC
 SG_ M2P_SysMaxVolt_B5_06 : 48|16@1+ (1,0) [0|65535] "mv"  PC

BO_ 2334977687 M2P_SUMDATA37__07: 8 MBMU
 SG_ M2P_Power_B5_07 : 0|16@1+ (1,-20000) [-20000|45535] "Kw"  PC
 SG_ M2P_SysremEngy_Chg_B5_07 : 16|16@1+ (1,0) [0|65535] "Kwh"  PC
 SG_ M2P_SysremEngy_DisChg_B5_07 : 32|16@1+ (1,0) [0|65535] "Kwh"  PC
 SG_ M2P_SysMaxVolt_B5_07 : 48|16@1+ (1,0) [0|65535] "mv"  PC

BO_ 2334977688 M2P_SUMDATA37__08: 8 MBMU
 SG_ M2P_Power_B5_08 : 0|16@1+ (1,-20000) [-20000|45535] "Kw"  PC
 SG_ M2P_SysremEngy_Chg_B5_08 : 16|16@1+ (1,0) [0|65535] "Kwh"  PC
 SG_ M2P_SysremEngy_DisChg_B5_08 : 32|16@1+ (1,0) [0|65535] "Kwh"  PC
 SG_ M2P_SysMaxVolt_B5_08 : 48|16@1+ (1,0) [0|65535] "mv"  PC

BO_ 2334977689 M2P_SUMDATA37__09: 8 MBMU
 SG_ M2P_Power_B5_09 : 0|16@1+ (1,-20000) [-20000|45535] "Kw"  PC
 SG_ M2P_SysremEngy_Chg_B5_09 : 16|16@1+ (1,0) [0|65535] "Kwh"  PC
 SG_ M2P_SysremEngy_DisChg_B5_09 : 32|16@1+ (1,0) [0|65535] "Kwh"  PC
 SG_ M2P_SysMaxVolt_B5_09 : 48|16@1+ (1,0) [0|65535] "mv"  PC

BO_ 2334977690 M2P_SUMDATA37__10: 8 MBMU
 SG_ M2P_Power_B5_10 : 0|16@1+ (1,-20000) [-20000|45535] "Kw"  PC
 SG_ M2P_SysremEngy_Chg_B5_10 : 16|16@1+ (1,0) [0|65535] "Kwh"  PC
 SG_ M2P_SysremEngy_DisChg_B5_10 : 32|16@1+ (1,0) [0|65535] "Kwh"  PC
 SG_ M2P_SysMaxVolt_B5_10 : 48|16@1+ (1,0) [0|65535] "mv"  PC

BO_ 2334977691 M2P_SUMDATA37__11: 8 MBMU
 SG_ M2P_Power_B5_11 : 0|16@1+ (1,-20000) [-20000|45535] "Kw"  PC
 SG_ M2P_SysremEngy_Chg_B5_11 : 16|16@1+ (1,0) [0|65535] "Kwh"  PC
 SG_ M2P_SysremEngy_DisChg_B5_11 : 32|16@1+ (1,0) [0|65535] "Kwh"  PC
 SG_ M2P_SysMaxVolt_B5_11 : 48|16@1+ (1,0) [0|65535] "mv"  PC

BO_ 2334977692 M2P_SUMDATA37__12: 8 MBMU
 SG_ M2P_Power_B5_12 : 0|16@1+ (1,-20000) [-20000|45535] "Kw"  PC
 SG_ M2P_SysremEngy_Chg_B5_12 : 16|16@1+ (1,0) [0|65535] "Kwh"  PC
 SG_ M2P_SysremEngy_DisChg_B5_12 : 32|16@1+ (1,0) [0|65535] "Kwh"  PC
 SG_ M2P_SysMaxVolt_B5_12 : 48|16@1+ (1,0) [0|65535] "mv"  PC

BO_ 2334977693 M2P_SUMDATA37__13: 8 MBMU
 SG_ M2P_Power_B5_13 : 0|16@1+ (1,-20000) [-20000|45535] "Kw"  PC
 SG_ M2P_SysremEngy_Chg_B5_13 : 16|16@1+ (1,0) [0|65535] "Kwh"  PC
 SG_ M2P_SysremEngy_DisChg_B5_13 : 32|16@1+ (1,0) [0|65535] "Kwh"  PC
 SG_ M2P_SysMaxVolt_B5_13 : 48|16@1+ (1,0) [0|65535] "mv"  PC

BO_ 2334977694 M2P_SUMDATA37__14: 8 MBMU
 SG_ M2P_Power_B5_14 : 0|16@1+ (1,-20000) [-20000|45535] "Kw"  PC
 SG_ M2P_SysremEngy_Chg_B5_14 : 16|16@1+ (1,0) [0|65535] "Kwh"  PC
 SG_ M2P_SysremEngy_DisChg_B5_14 : 32|16@1+ (1,0) [0|65535] "Kwh"  PC
 SG_ M2P_SysMaxVolt_B5_14 : 48|16@1+ (1,0) [0|65535] "mv"  PC

BO_ 2334977695 M2P_SUMDATA37__15: 8 MBMU
 SG_ M2P_Power_B5_15 : 0|16@1+ (1,-20000) [-20000|45535] "Kw"  PC
 SG_ M2P_SysremEngy_Chg_B5_15 : 16|16@1+ (1,0) [0|65535] "Kwh"  PC
 SG_ M2P_SysremEngy_DisChg_B5_15 : 32|16@1+ (1,0) [0|65535] "Kwh"  PC
 SG_ M2P_SysMaxVolt_B5_15 : 48|16@1+ (1,0) [0|65535] "mv"  PC

BO_ 2334977696 M2P_SUMDATA37__16: 8 MBMU
 SG_ M2P_Power_B5_16 : 0|16@1+ (1,-20000) [-20000|45535] "Kw"  PC
 SG_ M2P_SysremEngy_Chg_B5_16 : 16|16@1+ (1,0) [0|65535] "Kwh"  PC
 SG_ M2P_SysremEngy_DisChg_B5_16 : 32|16@1+ (1,0) [0|65535] "Kwh"  PC
 SG_ M2P_SysMaxVolt_B5_16 : 48|16@1+ (1,0) [0|65535] "mv"  PC

BO_ 2334977697 M2P_SUMDATA37__17: 8 MBMU
 SG_ M2P_Power_B5_17 : 0|16@1+ (1,-20000) [-20000|45535] "Kw"  PC
 SG_ M2P_SysremEngy_Chg_B5_17 : 16|16@1+ (1,0) [0|65535] "Kwh"  PC
 SG_ M2P_SysremEngy_DisChg_B5_17 : 32|16@1+ (1,0) [0|65535] "Kwh"  PC
 SG_ M2P_SysMaxVolt_B5_17 : 48|16@1+ (1,0) [0|65535] "mv"  PC

BO_ 2334977698 M2P_SUMDATA37__18: 8 MBMU
 SG_ M2P_Power_B5_18 : 0|16@1+ (1,-20000) [-20000|45535] "Kw"  PC
 SG_ M2P_SysremEngy_Chg_B5_18 : 16|16@1+ (1,0) [0|65535] "Kwh"  PC
 SG_ M2P_SysremEngy_DisChg_B5_18 : 32|16@1+ (1,0) [0|65535] "Kwh"  PC
 SG_ M2P_SysMaxVolt_B5_18 : 48|16@1+ (1,0) [0|65535] "mv"  PC

BO_ 2334977699 M2P_SUMDATA37__19: 8 MBMU
 SG_ M2P_Power_B5_19 : 0|16@1+ (1,-20000) [-20000|45535] "Kw"  PC
 SG_ M2P_SysremEngy_Chg_B5_19 : 16|16@1+ (1,0) [0|65535] "Kwh"  PC
 SG_ M2P_SysremEngy_DisChg_B5_19 : 32|16@1+ (1,0) [0|65535] "Kwh"  PC
 SG_ M2P_SysMaxVolt_B5_19 : 48|16@1+ (1,0) [0|65535] "mv"  PC

BO_ 2334977700 M2P_SUMDATA37__20: 8 MBMU
 SG_ M2P_Power_B5_20 : 0|16@1+ (1,-20000) [-20000|45535] "Kw"  PC
 SG_ M2P_SysremEngy_Chg_B5_20 : 16|16@1+ (1,0) [0|65535] "Kwh"  PC
 SG_ M2P_SysremEngy_DisChg_B5_20 : 32|16@1+ (1,0) [0|65535] "Kwh"  PC
 SG_ M2P_SysMaxVolt_B5_20 : 48|16@1+ (1,0) [0|65535] "mv"  PC

BO_ 2334977701 M2P_SUMDATA37__21: 8 MBMU
 SG_ M2P_Power_B5_21 : 0|16@1+ (1,-20000) [-20000|45535] "Kw"  PC
 SG_ M2P_SysremEngy_Chg_B5_21 : 16|16@1+ (1,0) [0|65535] "Kwh"  PC
 SG_ M2P_SysremEngy_DisChg_B5_21 : 32|16@1+ (1,0) [0|65535] "Kwh"  PC
 SG_ M2P_SysMaxVolt_B5_21 : 48|16@1+ (1,0) [0|65535] "mv"  PC

BO_ 2334977702 M2P_SUMDATA37__22: 8 MBMU
 SG_ M2P_Power_B5_22 : 0|16@1+ (1,-20000) [-20000|45535] "Kw"  PC
 SG_ M2P_SysremEngy_Chg_B5_22 : 16|16@1+ (1,0) [0|65535] "Kwh"  PC
 SG_ M2P_SysremEngy_DisChg_B5_22 : 32|16@1+ (1,0) [0|65535] "Kwh"  PC
 SG_ M2P_SysMaxVolt_B5_22 : 48|16@1+ (1,0) [0|65535] "mv"  PC

BO_ 2334977703 M2P_SUMDATA37__23: 8 MBMU
 SG_ M2P_Power_B5_23 : 0|16@1+ (1,-20000) [-20000|45535] "Kw"  PC
 SG_ M2P_SysremEngy_Chg_B5_23 : 16|16@1+ (1,0) [0|65535] "Kwh"  PC
 SG_ M2P_SysremEngy_DisChg_B5_23 : 32|16@1+ (1,0) [0|65535] "Kwh"  PC
 SG_ M2P_SysMaxVolt_B5_23 : 48|16@1+ (1,0) [0|65535] "mv"  PC

BO_ 2334977704 M2P_SUMDATA37__24: 8 MBMU
 SG_ M2P_Power_B5_24 : 0|16@1+ (1,-20000) [-20000|45535] "Kw"  PC
 SG_ M2P_SysremEngy_Chg_B5_24 : 16|16@1+ (1,0) [0|65535] "Kwh"  PC
 SG_ M2P_SysremEngy_DisChg_B5_24 : 32|16@1+ (1,0) [0|65535] "Kwh"  PC
 SG_ M2P_SysMaxVolt_B5_24 : 48|16@1+ (1,0) [0|65535] "mv"  PC

BO_ 2334977705 M2P_SUMDATA37__25: 8 MBMU
 SG_ M2P_Power_B5_25 : 0|16@1+ (1,-20000) [-20000|45535] "Kw"  PC
 SG_ M2P_SysremEngy_Chg_B5_25 : 16|16@1+ (1,0) [0|65535] "Kwh"  PC
 SG_ M2P_SysremEngy_DisChg_B5_25 : 32|16@1+ (1,0) [0|65535] "Kwh"  PC
 SG_ M2P_SysMaxVolt_B5_25 : 48|16@1+ (1,0) [0|65535] "mv"  PC

BO_ 2334977706 M2P_SUMDATA37__26: 8 MBMU
 SG_ M2P_Power_B5_26 : 0|16@1+ (1,-20000) [-20000|45535] "Kw"  PC
 SG_ M2P_SysremEngy_Chg_B5_26 : 16|16@1+ (1,0) [0|65535] "Kwh"  PC
 SG_ M2P_SysremEngy_DisChg_B5_26 : 32|16@1+ (1,0) [0|65535] "Kwh"  PC
 SG_ M2P_SysMaxVolt_B5_26 : 48|16@1+ (1,0) [0|65535] "mv"  PC

BO_ 2334977707 M2P_SUMDATA37__27: 8 MBMU
 SG_ M2P_Power_B5_27 : 0|16@1+ (1,-20000) [-20000|45535] "Kw"  PC
 SG_ M2P_SysremEngy_Chg_B5_27 : 16|16@1+ (1,0) [0|65535] "Kwh"  PC
 SG_ M2P_SysremEngy_DisChg_B5_27 : 32|16@1+ (1,0) [0|65535] "Kwh"  PC
 SG_ M2P_SysMaxVolt_B5_27 : 48|16@1+ (1,0) [0|65535] "mv"  PC

BO_ 2334977708 M2P_SUMDATA37__28: 8 MBMU
 SG_ M2P_Power_B5_28 : 0|16@1+ (1,-20000) [-20000|45535] "Kw"  PC
 SG_ M2P_SysremEngy_Chg_B5_28 : 16|16@1+ (1,0) [0|65535] "Kwh"  PC
 SG_ M2P_SysremEngy_DisChg_B5_28 : 32|16@1+ (1,0) [0|65535] "Kwh"  PC
 SG_ M2P_SysMaxVolt_B5_28 : 48|16@1+ (1,0) [0|65535] "mv"  PC

BO_ 2334977709 M2P_SUMDATA37__29: 8 MBMU
 SG_ M2P_Power_B5_29 : 0|16@1+ (1,-20000) [-20000|45535] "Kw"  PC
 SG_ M2P_SysremEngy_Chg_B5_29 : 16|16@1+ (1,0) [0|65535] "Kwh"  PC
 SG_ M2P_SysremEngy_DisChg_B5_29 : 32|16@1+ (1,0) [0|65535] "Kwh"  PC
 SG_ M2P_SysMaxVolt_B5_29 : 48|16@1+ (1,0) [0|65535] "mv"  PC

BO_ 2334977710 M2P_SUMDATA37__30: 8 MBMU
 SG_ M2P_Power_B5_30 : 0|16@1+ (1,-20000) [-20000|45535] "Kw"  PC
 SG_ M2P_SysremEngy_Chg_B5_30 : 16|16@1+ (1,0) [0|65535] "Kwh"  PC
 SG_ M2P_SysremEngy_DisChg_B5_30 : 32|16@1+ (1,0) [0|65535] "Kwh"  PC
 SG_ M2P_SysMaxVolt_B5_30 : 48|16@1+ (1,0) [0|65535] "mv"  PC

BO_ 2334977711 M2P_SUMDATA37__31: 8 MBMU
 SG_ M2P_Power_B5_31 : 0|16@1+ (1,-20000) [-20000|45535] "Kw"  PC
 SG_ M2P_SysremEngy_Chg_B5_31 : 16|16@1+ (1,0) [0|65535] "Kwh"  PC
 SG_ M2P_SysremEngy_DisChg_B5_31 : 32|16@1+ (1,0) [0|65535] "Kwh"  PC
 SG_ M2P_SysMaxVolt_B5_31 : 48|16@1+ (1,0) [0|65535] "mv"  PC

BO_ 2335043217 M2P_SUMDATA38__01: 8 MBMU
 SG_ M2P_SysMinVolt_B5_01 : 0|16@1+ (1,0) [0|65535] "mv"  PC
 SG_ M2P_SysAvgVolt_B5_01 : 16|16@1+ (1,0) [0|65535] "mv"  PC
 SG_ M2P_BMS_Status_B5 : 32|3@1+ (1,0) [0|7] ""  PC
 SG_ M2P_SOC_B5 : 35|10@1+ (0.1,0) [0|102.3] "%"  PC
 SG_ M2P_SOH_B5 : 45|8@1+ (1,0) [0|255] "%"  PC
 SG_ Reserved_01 : 53|11@1+ (1,0) [0|2047] ""  PC

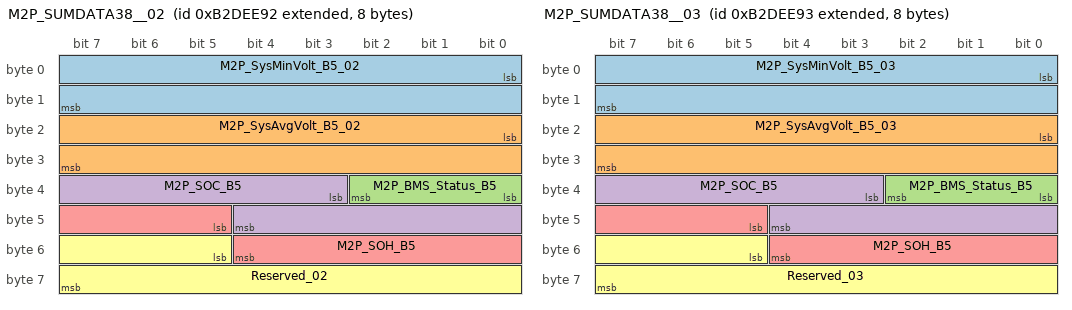
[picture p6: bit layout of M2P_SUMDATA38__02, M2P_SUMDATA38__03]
BO_ 2335043218 M2P_SUMDATA38__02: 8 MBMU
 SG_ M2P_SysMinVolt_B5_02 : 0|16@1+ (1,0) [0|65535] "mv"  PC
 SG_ M2P_SysAvgVolt_B5_02 : 16|16@1+ (1,0) [0|65535] "mv"  PC
 SG_ M2P_BMS_Status_B5 : 32|3@1+ (1,0) [0|7] ""  PC
 SG_ M2P_SOC_B5 : 35|10@1+ (0.1,0) [0|102.3] "%"  PC
 SG_ M2P_SOH_B5 : 45|8@1+ (1,0) [0|255] "%"  PC
 SG_ Reserved_02 : 53|11@1+ (1,0) [0|2047] ""  PC

BO_ 2335043219 M2P_SUMDATA38__03: 8 MBMU
 SG_ M2P_SysMinVolt_B5_03 : 0|16@1+ (1,0) [0|65535] "mv"  PC
 SG_ M2P_SysAvgVolt_B5_03 : 16|16@1+ (1,0) [0|65535] "mv"  PC
 SG_ M2P_BMS_Status_B5 : 32|3@1+ (1,0) [0|7] ""  PC
 SG_ M2P_SOC_B5 : 35|10@1+ (0.1,0) [0|102.3] "%"  PC
 SG_ M2P_SOH_B5 : 45|8@1+ (1,0) [0|255] "%"  PC
 SG_ Reserved_03 : 53|11@1+ (1,0) [0|2047] ""  PC

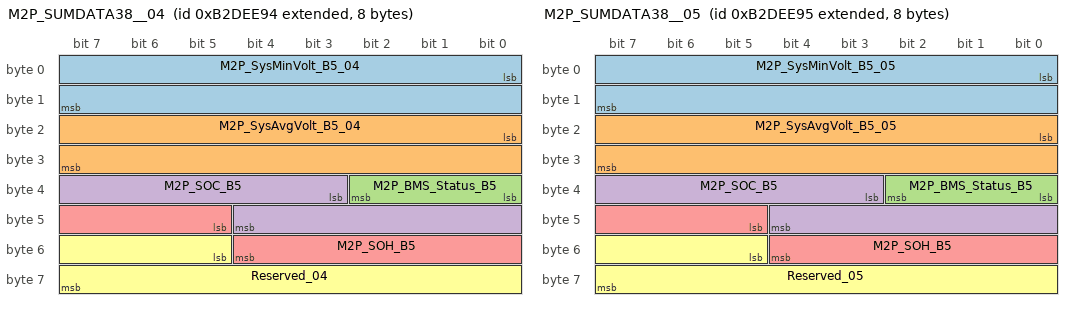
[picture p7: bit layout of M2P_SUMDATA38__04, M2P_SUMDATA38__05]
BO_ 2335043220 M2P_SUMDATA38__04: 8 MBMU
 SG_ M2P_SysMinVolt_B5_04 : 0|16@1+ (1,0) [0|65535] "mv"  PC
 SG_ M2P_SysAvgVolt_B5_04 : 16|16@1+ (1,0) [0|65535] "mv"  PC
 SG_ M2P_BMS_Status_B5 : 32|3@1+ (1,0) [0|7] ""  PC
 SG_ M2P_SOC_B5 : 35|10@1+ (0.1,0) [0|102.3] "%"  PC
 SG_ M2P_SOH_B5 : 45|8@1+ (1,0) [0|255] "%"  PC
 SG_ Reserved_04 : 53|11@1+ (1,0) [0|2047] ""  PC

BO_ 2335043221 M2P_SUMDATA38__05: 8 MBMU
 SG_ M2P_SysMinVolt_B5_05 : 0|16@1+ (1,0) [0|65535] "mv"  PC
 SG_ M2P_SysAvgVolt_B5_05 : 16|16@1+ (1,0) [0|65535] "mv"  PC
 SG_ M2P_BMS_Status_B5 : 32|3@1+ (1,0) [0|7] ""  PC
 SG_ M2P_SOC_B5 : 35|10@1+ (0.1,0) [0|102.3] "%"  PC
 SG_ M2P_SOH_B5 : 45|8@1+ (1,0) [0|255] "%"  PC
 SG_ Reserved_05 : 53|11@1+ (1,0) [0|2047] ""  PC

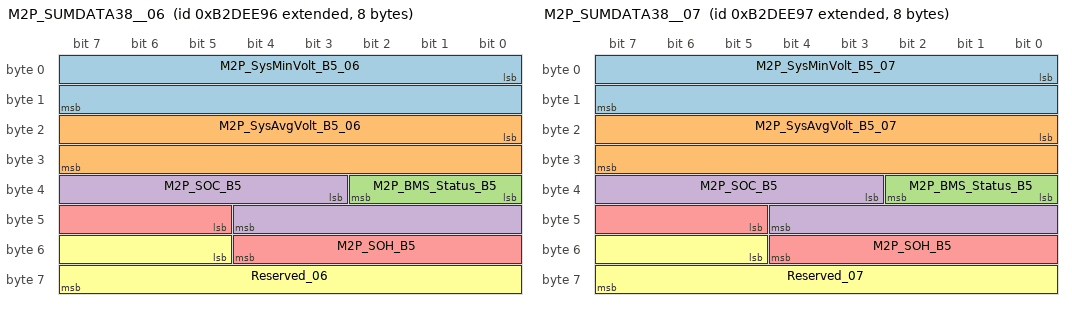
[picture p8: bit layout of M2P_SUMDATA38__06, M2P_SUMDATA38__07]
BO_ 2335043222 M2P_SUMDATA38__06: 8 MBMU
 SG_ M2P_SysMinVolt_B5_06 : 0|16@1+ (1,0) [0|65535] "mv"  PC
 SG_ M2P_SysAvgVolt_B5_06 : 16|16@1+ (1,0) [0|65535] "mv"  PC
 SG_ M2P_BMS_Status_B5 : 32|3@1+ (1,0) [0|7] ""  PC
 SG_ M2P_SOC_B5 : 35|10@1+ (0.1,0) [0|102.3] "%"  PC
 SG_ M2P_SOH_B5 : 45|8@1+ (1,0) [0|255] "%"  PC
 SG_ Reserved_06 : 53|11@1+ (1,0) [0|2047] ""  PC

BO_ 2335043223 M2P_SUMDATA38__07: 8 MBMU
 SG_ M2P_SysMinVolt_B5_07 : 0|16@1+ (1,0) [0|65535] "mv"  PC
 SG_ M2P_SysAvgVolt_B5_07 : 16|16@1+ (1,0) [0|65535] "mv"  PC
 SG_ M2P_BMS_Status_B5 : 32|3@1+ (1,0) [0|7] ""  PC
 SG_ M2P_SOC_B5 : 35|10@1+ (0.1,0) [0|102.3] "%"  PC
 SG_ M2P_SOH_B5 : 45|8@1+ (1,0) [0|255] "%"  PC
 SG_ Reserved_07 : 53|11@1+ (1,0) [0|2047] ""  PC

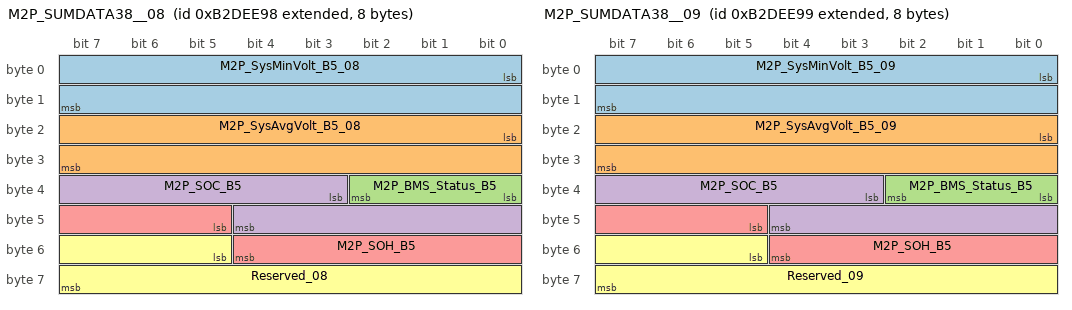
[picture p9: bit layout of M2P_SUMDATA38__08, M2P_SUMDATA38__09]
BO_ 2335043224 M2P_SUMDATA38__08: 8 MBMU
 SG_ M2P_SysMinVolt_B5_08 : 0|16@1+ (1,0) [0|65535] "mv"  PC
 SG_ M2P_SysAvgVolt_B5_08 : 16|16@1+ (1,0) [0|65535] "mv"  PC
 SG_ M2P_BMS_Status_B5 : 32|3@1+ (1,0) [0|7] ""  PC
 SG_ M2P_SOC_B5 : 35|10@1+ (0.1,0) [0|102.3] "%"  PC
 SG_ M2P_SOH_B5 : 45|8@1+ (1,0) [0|255] "%"  PC
 SG_ Reserved_08 : 53|11@1+ (1,0) [0|2047] ""  PC

BO_ 2335043225 M2P_SUMDATA38__09: 8 MBMU
 SG_ M2P_SysMinVolt_B5_09 : 0|16@1+ (1,0) [0|65535] "mv"  PC
 SG_ M2P_SysAvgVolt_B5_09 : 16|16@1+ (1,0) [0|65535] "mv"  PC
 SG_ M2P_BMS_Status_B5 : 32|3@1+ (1,0) [0|7] ""  PC
 SG_ M2P_SOC_B5 : 35|10@1+ (0.1,0) [0|102.3] "%"  PC
 SG_ M2P_SOH_B5 : 45|8@1+ (1,0) [0|255] "%"  PC
 SG_ Reserved_09 : 53|11@1+ (1,0) [0|2047] ""  PC

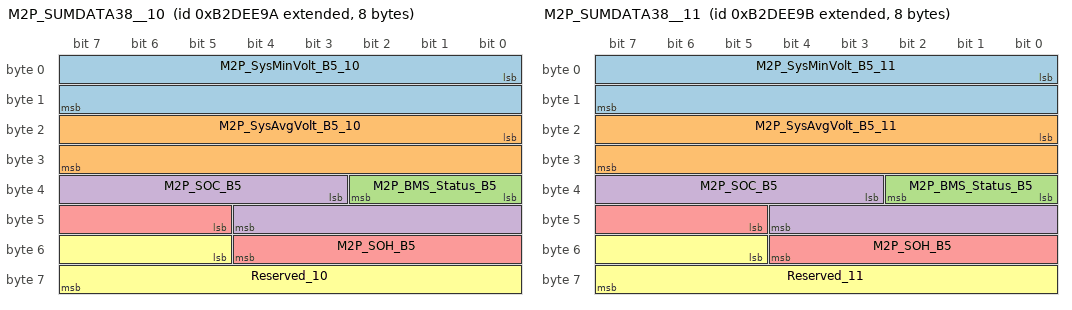
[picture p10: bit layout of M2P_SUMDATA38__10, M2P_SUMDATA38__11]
BO_ 2335043226 M2P_SUMDATA38__10: 8 MBMU
 SG_ M2P_SysMinVolt_B5_10 : 0|16@1+ (1,0) [0|65535] "mv"  PC
 SG_ M2P_SysAvgVolt_B5_10 : 16|16@1+ (1,0) [0|65535] "mv"  PC
 SG_ M2P_BMS_Status_B5 : 32|3@1+ (1,0) [0|7] ""  PC
 SG_ M2P_SOC_B5 : 35|10@1+ (0.1,0) [0|102.3] "%"  PC
 SG_ M2P_SOH_B5 : 45|8@1+ (1,0) [0|255] "%"  PC
 SG_ Reserved_10 : 53|11@1+ (1,0) [0|2047] ""  PC

BO_ 2335043227 M2P_SUMDATA38__11: 8 MBMU
 SG_ M2P_SysMinVolt_B5_11 : 0|16@1+ (1,0) [0|65535] "mv"  PC
 SG_ M2P_SysAvgVolt_B5_11 : 16|16@1+ (1,0) [0|65535] "mv"  PC
 SG_ M2P_BMS_Status_B5 : 32|3@1+ (1,0) [0|7] ""  PC
 SG_ M2P_SOC_B5 : 35|10@1+ (0.1,0) [0|102.3] "%"  PC
 SG_ M2P_SOH_B5 : 45|8@1+ (1,0) [0|255] "%"  PC
 SG_ Reserved_11 : 53|11@1+ (1,0) [0|2047] ""  PC

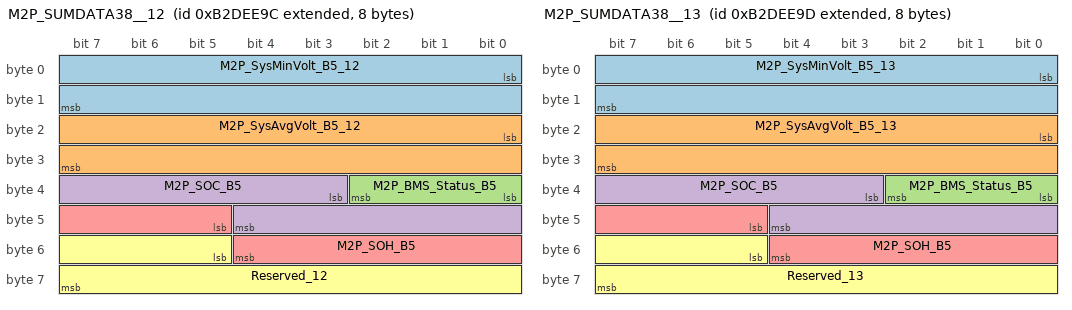
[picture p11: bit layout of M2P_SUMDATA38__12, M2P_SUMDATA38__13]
BO_ 2335043228 M2P_SUMDATA38__12: 8 MBMU
 SG_ M2P_SysMinVolt_B5_12 : 0|16@1+ (1,0) [0|65535] "mv"  PC
 SG_ M2P_SysAvgVolt_B5_12 : 16|16@1+ (1,0) [0|65535] "mv"  PC
 SG_ M2P_BMS_Status_B5 : 32|3@1+ (1,0) [0|7] ""  PC
 SG_ M2P_SOC_B5 : 35|10@1+ (0.1,0) [0|102.3] "%"  PC
 SG_ M2P_SOH_B5 : 45|8@1+ (1,0) [0|255] "%"  PC
 SG_ Reserved_12 : 53|11@1+ (1,0) [0|2047] ""  PC

BO_ 2335043229 M2P_SUMDATA38__13: 8 MBMU
 SG_ M2P_SysMinVolt_B5_13 : 0|16@1+ (1,0) [0|65535] "mv"  PC
 SG_ M2P_SysAvgVolt_B5_13 : 16|16@1+ (1,0) [0|65535] "mv"  PC
 SG_ M2P_BMS_Status_B5 : 32|3@1+ (1,0) [0|7] ""  PC
 SG_ M2P_SOC_B5 : 35|10@1+ (0.1,0) [0|102.3] "%"  PC
 SG_ M2P_SOH_B5 : 45|8@1+ (1,0) [0|255] "%"  PC
 SG_ Reserved_13 : 53|11@1+ (1,0) [0|2047] ""  PC

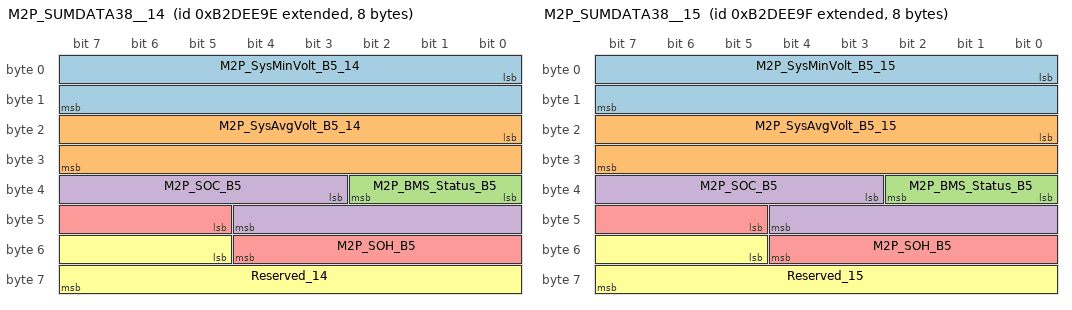
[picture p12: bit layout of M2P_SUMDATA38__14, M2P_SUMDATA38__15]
BO_ 2335043230 M2P_SUMDATA38__14: 8 MBMU
 SG_ M2P_SysMinVolt_B5_14 : 0|16@1+ (1,0) [0|65535] "mv"  PC
 SG_ M2P_SysAvgVolt_B5_14 : 16|16@1+ (1,0) [0|65535] "mv"  PC
 SG_ M2P_BMS_Status_B5 : 32|3@1+ (1,0) [0|7] ""  PC
 SG_ M2P_SOC_B5 : 35|10@1+ (0.1,0) [0|102.3] "%"  PC
 SG_ M2P_SOH_B5 : 45|8@1+ (1,0) [0|255] "%"  PC
 SG_ Reserved_14 : 53|11@1+ (1,0) [0|2047] ""  PC

BO_ 2335043231 M2P_SUMDATA38__15: 8 MBMU
 SG_ M2P_SysMinVolt_B5_15 : 0|16@1+ (1,0) [0|65535] "mv"  PC
 SG_ M2P_SysAvgVolt_B5_15 : 16|16@1+ (1,0) [0|65535] "mv"  PC
 SG_ M2P_BMS_Status_B5 : 32|3@1+ (1,0) [0|7] ""  PC
 SG_ M2P_SOC_B5 : 35|10@1+ (0.1,0) [0|102.3] "%"  PC
 SG_ M2P_SOH_B5 : 45|8@1+ (1,0) [0|255] "%"  PC
 SG_ Reserved_15 : 53|11@1+ (1,0) [0|2047] ""  PC

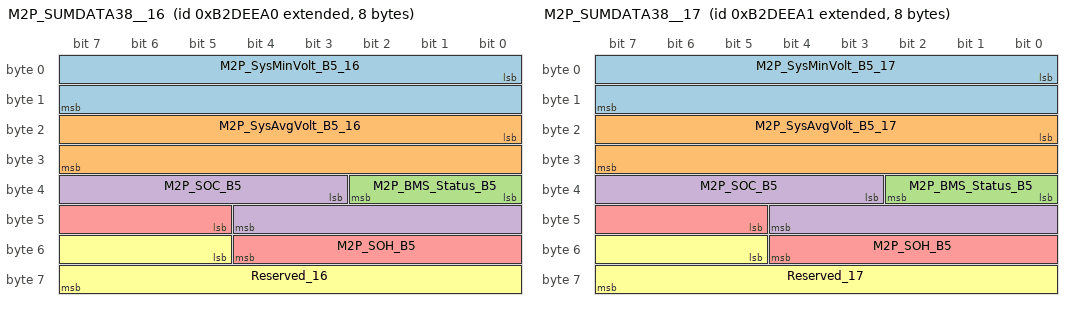
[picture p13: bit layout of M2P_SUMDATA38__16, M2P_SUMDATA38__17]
BO_ 2335043232 M2P_SUMDATA38__16: 8 MBMU
 SG_ M2P_SysMinVolt_B5_16 : 0|16@1+ (1,0) [0|65535] "mv"  PC
 SG_ M2P_SysAvgVolt_B5_16 : 16|16@1+ (1,0) [0|65535] "mv"  PC
 SG_ M2P_BMS_Status_B5 : 32|3@1+ (1,0) [0|7] ""  PC
 SG_ M2P_SOC_B5 : 35|10@1+ (0.1,0) [0|102.3] "%"  PC
 SG_ M2P_SOH_B5 : 45|8@1+ (1,0) [0|255] "%"  PC
 SG_ Reserved_16 : 53|11@1+ (1,0) [0|2047] ""  PC

BO_ 2335043233 M2P_SUMDATA38__17: 8 MBMU
 SG_ M2P_SysMinVolt_B5_17 : 0|16@1+ (1,0) [0|65535] "mv"  PC
 SG_ M2P_SysAvgVolt_B5_17 : 16|16@1+ (1,0) [0|65535] "mv"  PC
 SG_ M2P_BMS_Status_B5 : 32|3@1+ (1,0) [0|7] ""  PC
 SG_ M2P_SOC_B5 : 35|10@1+ (0.1,0) [0|102.3] "%"  PC
 SG_ M2P_SOH_B5 : 45|8@1+ (1,0) [0|255] "%"  PC
 SG_ Reserved_17 : 53|11@1+ (1,0) [0|2047] ""  PC

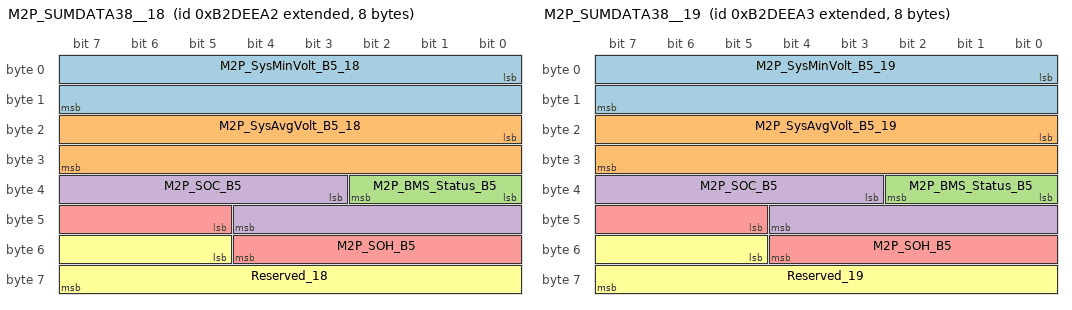
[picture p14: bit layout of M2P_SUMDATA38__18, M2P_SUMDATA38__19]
BO_ 2335043234 M2P_SUMDATA38__18: 8 MBMU
 SG_ M2P_SysMinVolt_B5_18 : 0|16@1+ (1,0) [0|65535] "mv"  PC
 SG_ M2P_SysAvgVolt_B5_18 : 16|16@1+ (1,0) [0|65535] "mv"  PC
 SG_ M2P_BMS_Status_B5 : 32|3@1+ (1,0) [0|7] ""  PC
 SG_ M2P_SOC_B5 : 35|10@1+ (0.1,0) [0|102.3] "%"  PC
 SG_ M2P_SOH_B5 : 45|8@1+ (1,0) [0|255] "%"  PC
 SG_ Reserved_18 : 53|11@1+ (1,0) [0|2047] ""  PC

BO_ 2335043235 M2P_SUMDATA38__19: 8 MBMU
 SG_ M2P_SysMinVolt_B5_19 : 0|16@1+ (1,0) [0|65535] "mv"  PC
 SG_ M2P_SysAvgVolt_B5_19 : 16|16@1+ (1,0) [0|65535] "mv"  PC
 SG_ M2P_BMS_Status_B5 : 32|3@1+ (1,0) [0|7] ""  PC
 SG_ M2P_SOC_B5 : 35|10@1+ (0.1,0) [0|102.3] "%"  PC
 SG_ M2P_SOH_B5 : 45|8@1+ (1,0) [0|255] "%"  PC
 SG_ Reserved_19 : 53|11@1+ (1,0) [0|2047] ""  PC

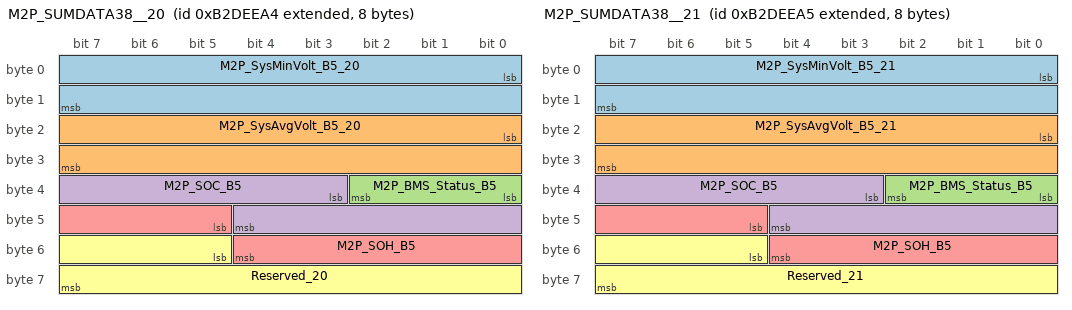
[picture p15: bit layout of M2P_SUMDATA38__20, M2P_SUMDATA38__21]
BO_ 2335043236 M2P_SUMDATA38__20: 8 MBMU
 SG_ M2P_SysMinVolt_B5_20 : 0|16@1+ (1,0) [0|65535] "mv"  PC
 SG_ M2P_SysAvgVolt_B5_20 : 16|16@1+ (1,0) [0|65535] "mv"  PC
 SG_ M2P_BMS_Status_B5 : 32|3@1+ (1,0) [0|7] ""  PC
 SG_ M2P_SOC_B5 : 35|10@1+ (0.1,0) [0|102.3] "%"  PC
 SG_ M2P_SOH_B5 : 45|8@1+ (1,0) [0|255] "%"  PC
 SG_ Reserved_20 : 53|11@1+ (1,0) [0|2047] ""  PC

BO_ 2335043237 M2P_SUMDATA38__21: 8 MBMU
 SG_ M2P_SysMinVolt_B5_21 : 0|16@1+ (1,0) [0|65535] "mv"  PC
 SG_ M2P_SysAvgVolt_B5_21 : 16|16@1+ (1,0) [0|65535] "mv"  PC
 SG_ M2P_BMS_Status_B5 : 32|3@1+ (1,0) [0|7] ""  PC
 SG_ M2P_SOC_B5 : 35|10@1+ (0.1,0) [0|102.3] "%"  PC
 SG_ M2P_SOH_B5 : 45|8@1+ (1,0) [0|255] "%"  PC
 SG_ Reserved_21 : 53|11@1+ (1,0) [0|2047] ""  PC

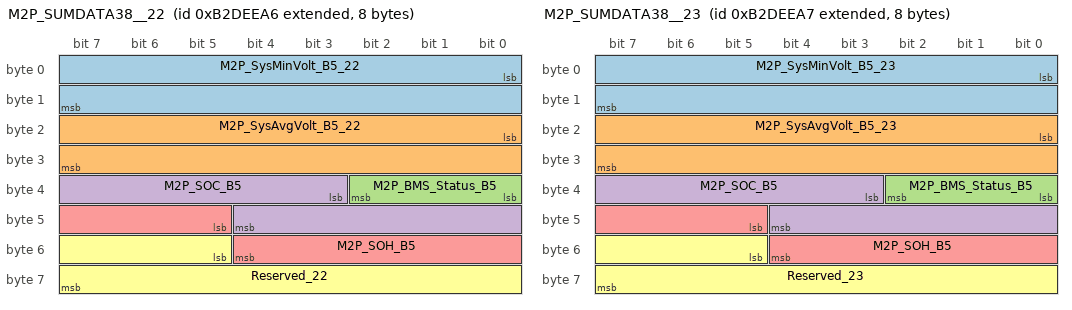
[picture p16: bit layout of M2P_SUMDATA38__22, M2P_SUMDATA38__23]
BO_ 2335043238 M2P_SUMDATA38__22: 8 MBMU
 SG_ M2P_SysMinVolt_B5_22 : 0|16@1+ (1,0) [0|65535] "mv"  PC
 SG_ M2P_SysAvgVolt_B5_22 : 16|16@1+ (1,0) [0|65535] "mv"  PC
 SG_ M2P_BMS_Status_B5 : 32|3@1+ (1,0) [0|7] ""  PC
 SG_ M2P_SOC_B5 : 35|10@1+ (0.1,0) [0|102.3] "%"  PC
 SG_ M2P_SOH_B5 : 45|8@1+ (1,0) [0|255] "%"  PC
 SG_ Reserved_22 : 53|11@1+ (1,0) [0|2047] ""  PC

BO_ 2335043239 M2P_SUMDATA38__23: 8 MBMU
 SG_ M2P_SysMinVolt_B5_23 : 0|16@1+ (1,0) [0|65535] "mv"  PC
 SG_ M2P_SysAvgVolt_B5_23 : 16|16@1+ (1,0) [0|65535] "mv"  PC
 SG_ M2P_BMS_Status_B5 : 32|3@1+ (1,0) [0|7] ""  PC
 SG_ M2P_SOC_B5 : 35|10@1+ (0.1,0) [0|102.3] "%"  PC
 SG_ M2P_SOH_B5 : 45|8@1+ (1,0) [0|255] "%"  PC
 SG_ Reserved_23 : 53|11@1+ (1,0) [0|2047] ""  PC

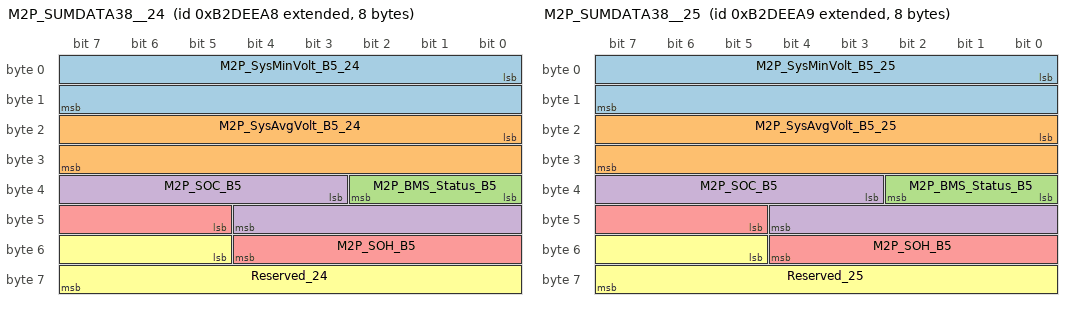
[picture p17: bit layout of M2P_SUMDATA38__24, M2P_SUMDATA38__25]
BO_ 2335043240 M2P_SUMDATA38__24: 8 MBMU
 SG_ M2P_SysMinVolt_B5_24 : 0|16@1+ (1,0) [0|65535] "mv"  PC
 SG_ M2P_SysAvgVolt_B5_24 : 16|16@1+ (1,0) [0|65535] "mv"  PC
 SG_ M2P_BMS_Status_B5 : 32|3@1+ (1,0) [0|7] ""  PC
 SG_ M2P_SOC_B5 : 35|10@1+ (0.1,0) [0|102.3] "%"  PC
 SG_ M2P_SOH_B5 : 45|8@1+ (1,0) [0|255] "%"  PC
 SG_ Reserved_24 : 53|11@1+ (1,0) [0|2047] ""  PC

BO_ 2335043241 M2P_SUMDATA38__25: 8 MBMU
 SG_ M2P_SysMinVolt_B5_25 : 0|16@1+ (1,0) [0|65535] "mv"  PC
 SG_ M2P_SysAvgVolt_B5_25 : 16|16@1+ (1,0) [0|65535] "mv"  PC
 SG_ M2P_BMS_Status_B5 : 32|3@1+ (1,0) [0|7] ""  PC
 SG_ M2P_SOC_B5 : 35|10@1+ (0.1,0) [0|102.3] "%"  PC
 SG_ M2P_SOH_B5 : 45|8@1+ (1,0) [0|255] "%"  PC
 SG_ Reserved_25 : 53|11@1+ (1,0) [0|2047] ""  PC

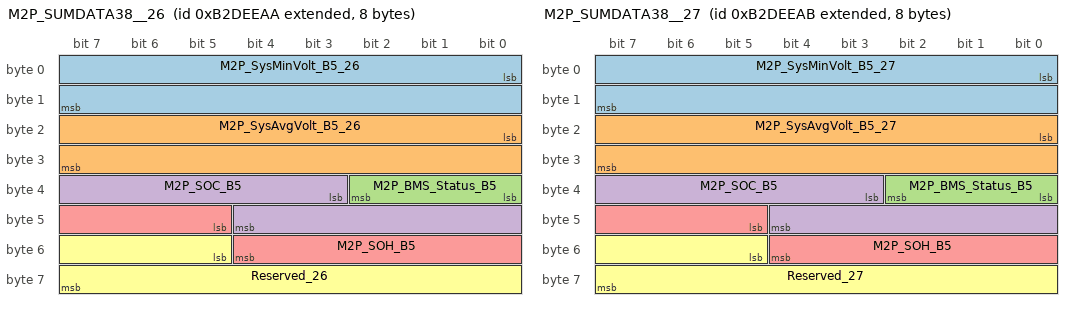
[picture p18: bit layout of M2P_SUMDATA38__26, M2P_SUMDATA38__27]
BO_ 2335043242 M2P_SUMDATA38__26: 8 MBMU
 SG_ M2P_SysMinVolt_B5_26 : 0|16@1+ (1,0) [0|65535] "mv"  PC
 SG_ M2P_SysAvgVolt_B5_26 : 16|16@1+ (1,0) [0|65535] "mv"  PC
 SG_ M2P_BMS_Status_B5 : 32|3@1+ (1,0) [0|7] ""  PC
 SG_ M2P_SOC_B5 : 35|10@1+ (0.1,0) [0|102.3] "%"  PC
 SG_ M2P_SOH_B5 : 45|8@1+ (1,0) [0|255] "%"  PC
 SG_ Reserved_26 : 53|11@1+ (1,0) [0|2047] ""  PC

BO_ 2335043243 M2P_SUMDATA38__27: 8 MBMU
 SG_ M2P_SysMinVolt_B5_27 : 0|16@1+ (1,0) [0|65535] "mv"  PC
 SG_ M2P_SysAvgVolt_B5_27 : 16|16@1+ (1,0) [0|65535] "mv"  PC
 SG_ M2P_BMS_Status_B5 : 32|3@1+ (1,0) [0|7] ""  PC
 SG_ M2P_SOC_B5 : 35|10@1+ (0.1,0) [0|102.3] "%"  PC
 SG_ M2P_SOH_B5 : 45|8@1+ (1,0) [0|255] "%"  PC
 SG_ Reserved_27 : 53|11@1+ (1,0) [0|2047] ""  PC

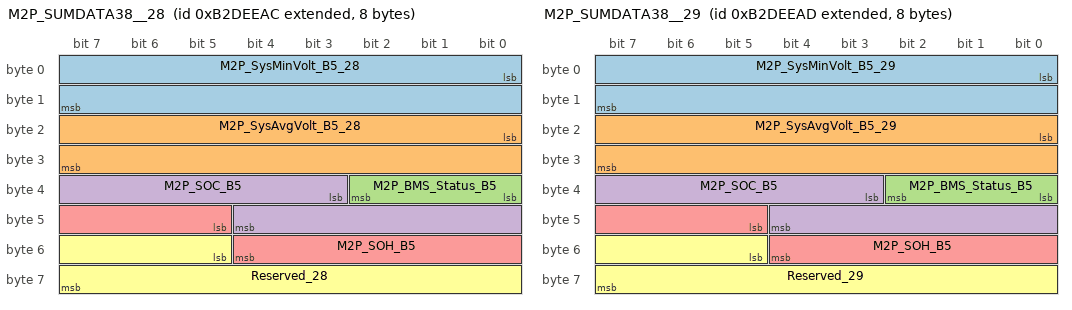
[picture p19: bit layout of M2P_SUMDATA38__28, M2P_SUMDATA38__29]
BO_ 2335043244 M2P_SUMDATA38__28: 8 MBMU
 SG_ M2P_SysMinVolt_B5_28 : 0|16@1+ (1,0) [0|65535] "mv"  PC
 SG_ M2P_SysAvgVolt_B5_28 : 16|16@1+ (1,0) [0|65535] "mv"  PC
 SG_ M2P_BMS_Status_B5 : 32|3@1+ (1,0) [0|7] ""  PC
 SG_ M2P_SOC_B5 : 35|10@1+ (0.1,0) [0|102.3] "%"  PC
 SG_ M2P_SOH_B5 : 45|8@1+ (1,0) [0|255] "%"  PC
 SG_ Reserved_28 : 53|11@1+ (1,0) [0|2047] ""  PC

BO_ 2335043245 M2P_SUMDATA38__29: 8 MBMU
 SG_ M2P_SysMinVolt_B5_29 : 0|16@1+ (1,0) [0|65535] "mv"  PC
 SG_ M2P_SysAvgVolt_B5_29 : 16|16@1+ (1,0) [0|65535] "mv"  PC
 SG_ M2P_BMS_Status_B5 : 32|3@1+ (1,0) [0|7] ""  PC
 SG_ M2P_SOC_B5 : 35|10@1+ (0.1,0) [0|102.3] "%"  PC
 SG_ M2P_SOH_B5 : 45|8@1+ (1,0) [0|255] "%"  PC
 SG_ Reserved_29 : 53|11@1+ (1,0) [0|2047] ""  PC

BO_ 2335043246 M2P_SUMDATA38__30: 8 MBMU
 SG_ M2P_SysMinVolt_B5_30 : 0|16@1+ (1,0) [0|65535] "mv"  PC
 SG_ M2P_SysAvgVolt_B5_30 : 16|16@1+ (1,0) [0|65535] "mv"  PC
 SG_ M2P_BMS_Status_B5 : 32|3@1+ (1,0) [0|7] ""  PC
 SG_ M2P_SOC_B5 : 35|10@1+ (0.1,0) [0|102.3] "%"  PC
 SG_ M2P_SOH_B5 : 45|8@1+ (1,0) [0|255] "%"  PC
 SG_ Reserved_30 : 53|11@1+ (1,0) [0|2047] ""  PC

BO_ 2335043247 M2P_SUMDATA38__31: 8 MBMU
 SG_ M2P_SysMinVolt_B5_31 : 0|16@1+ (1,0) [0|65535] "mv"  PC
 SG_ M2P_SysAvgVolt_B5_31 : 16|16@1+ (1,0) [0|65535] "mv"  PC
 SG_ M2P_BMS_Status_B5 : 32|3@1+ (1,0) [0|7] ""  PC
 SG_ M2P_SOC_B5 : 35|10@1+ (0.1,0) [0|102.3] "%"  PC
 SG_ M2P_SOH_B5 : 45|8@1+ (1,0) [0|255] "%"  PC
 SG_ Reserved_31 : 53|11@1+ (1,0) [0|2047] ""  PC

BO_ 2335108753 M2P_SUMDATA39__01: 8 MBMU
 SG_ M2P_SOE_Charge_B5 : 0|10@1+ (0.1,0) [0|102.3] "%"  PC
 SG_ M2P_SOE_Discharge_B5 : 10|10@1+ (0.1,0) [0|102.3] "%"  PC
 SG_ Reserved_01 : 20|44@1+ (1,0) [0|17592186044415] ""  PC

BO_ 2335108754 M2P_SUMDATA39__02: 8 MBMU
 SG_ M2P_SOE_Charge_B5 : 0|10@1+ (0.1,0) [0|102.3] "%"  PC
 SG_ M2P_SOE_Discharge_B5 : 10|10@1+ (0.1,0) [0|102.3] "%"  PC
 SG_ Reserved_02 : 20|44@1+ (1,0) [0|17592186044415] ""  PC

BO_ 2335108755 M2P_SUMDATA39__03: 8 MBMU
 SG_ M2P_SOE_Charge_B5 : 0|10@1+ (0.1,0) [0|102.3] "%"  PC
 SG_ M2P_SOE_Discharge_B5 : 10|10@1+ (0.1,0) [0|102.3] "%"  PC
 SG_ Reserved_03 : 20|44@1+ (1,0) [0|17592186044415] ""  PC

BO_ 2335108756 M2P_SUMDATA39__04: 8 MBMU
 SG_ M2P_SOE_Charge_B5 : 0|10@1+ (0.1,0) [0|102.3] "%"  PC
 SG_ M2P_SOE_Discharge_B5 : 10|10@1+ (0.1,0) [0|102.3] "%"  PC
 SG_ Reserved_04 : 20|44@1+ (1,0) [0|17592186044415] ""  PC

BO_ 2335108757 M2P_SUMDATA39__05: 8 MBMU
 SG_ M2P_SOE_Charge_B5 : 0|10@1+ (0.1,0) [0|102.3] "%"  PC
 SG_ M2P_SOE_Discharge_B5 : 10|10@1+ (0.1,0) [0|102.3] "%"  PC
 SG_ Reserved_05 : 20|44@1+ (1,0) [0|17592186044415] ""  PC

BO_ 2335108758 M2P_SUMDATA39__06: 8 MBMU
 SG_ M2P_SOE_Charge_B5 : 0|10@1+ (0.1,0) [0|102.3] "%"  PC
 SG_ M2P_SOE_Discharge_B5 : 10|10@1+ (0.1,0) [0|102.3] "%"  PC
 SG_ Reserved_06 : 20|44@1+ (1,0) [0|17592186044415] ""  PC

BO_ 2335108759 M2P_SUMDATA39__07: 8 MBMU
 SG_ M2P_SOE_Charge_B5 : 0|10@1+ (0.1,0) [0|102.3] "%"  PC
 SG_ M2P_SOE_Discharge_B5 : 10|10@1+ (0.1,0) [0|102.3] "%"  PC
 SG_ Reserved_07 : 20|44@1+ (1,0) [0|17592186044415] ""  PC

BO_ 2335108760 M2P_SUMDATA39__08: 8 MBMU
 SG_ M2P_SOE_Charge_B5 : 0|10@1+ (0.1,0) [0|102.3] "%"  PC
 SG_ M2P_SOE_Discharge_B5 : 10|10@1+ (0.1,0) [0|102.3] "%"  PC
 SG_ Reserved_08 : 20|44@1+ (1,0) [0|17592186044415] ""  PC

BO_ 2335108761 M2P_SUMDATA39__09: 8 MBMU
 SG_ M2P_SOE_Charge_B5 : 0|10@1+ (0.1,0) [0|102.3] "%"  PC
 SG_ M2P_SOE_Discharge_B5 : 10|10@1+ (0.1,0) [0|102.3] "%"  PC
 SG_ Reserved_09 : 20|44@1+ (1,0) [0|17592186044415] ""  PC

BO_ 2335108762 M2P_SUMDATA39__10: 8 MBMU
 SG_ M2P_SOE_Charge_B5 : 0|10@1+ (0.1,0) [0|102.3] "%"  PC
 SG_ M2P_SOE_Discharge_B5 : 10|10@1+ (0.1,0) [0|102.3] "%"  PC
 SG_ Reserved_10 : 20|44@1+ (1,0) [0|17592186044415] ""  PC

BO_ 2335108763 M2P_SUMDATA39__11: 8 MBMU
 SG_ M2P_SOE_Charge_B5 : 0|10@1+ (0.1,0) [0|102.3] "%"  PC
 SG_ M2P_SOE_Discharge_B5 : 10|10@1+ (0.1,0) [0|102.3] "%"  PC
 SG_ Reserved_11 : 20|44@1+ (1,0) [0|17592186044415] ""  PC

BO_ 2335108764 M2P_SUMDATA39__12: 8 MBMU
 SG_ M2P_SOE_Charge_B5 : 0|10@1+ (0.1,0) [0|102.3] "%"  PC
 SG_ M2P_SOE_Discharge_B5 : 10|10@1+ (0.1,0) [0|102.3] "%"  PC
 SG_ Reserved_12 : 20|44@1+ (1,0) [0|17592186044415] ""  PC

BO_ 2335108765 M2P_SUMDATA39__13: 8 MBMU
 SG_ M2P_SOE_Charge_B5 : 0|10@1+ (0.1,0) [0|102.3] "%"  PC
 SG_ M2P_SOE_Discharge_B5 : 10|10@1+ (0.1,0) [0|102.3] "%"  PC
 SG_ Reserved_13 : 20|44@1+ (1,0) [0|17592186044415] ""  PC

BO_ 2335108766 M2P_SUMDATA39__14: 8 MBMU
 SG_ M2P_SOE_Charge_B5 : 0|10@1+ (0.1,0) [0|102.3] "%"  PC
 SG_ M2P_SOE_Discharge_B5 : 10|10@1+ (0.1,0) [0|102.3] "%"  PC
 SG_ Reserved_14 : 20|44@1+ (1,0) [0|17592186044415] ""  PC

BO_ 2335108767 M2P_SUMDATA39__15: 8 MBMU
 SG_ M2P_SOE_Charge_B5 : 0|10@1+ (0.1,0) [0|102.3] "%"  PC
 SG_ M2P_SOE_Discharge_B5 : 10|10@1+ (0.1,0) [0|102.3] "%"  PC
 SG_ Reserved_15 : 20|44@1+ (1,0) [0|17592186044415] ""  PC

BO_ 2335108768 M2P_SUMDATA39__16: 8 MBMU
 SG_ M2P_SOE_Charge_B5 : 0|10@1+ (0.1,0) [0|102.3] "%"  PC
 SG_ M2P_SOE_Discharge_B5 : 10|10@1+ (0.1,0) [0|102.3] "%"  PC
 SG_ Reserved_16 : 20|44@1+ (1,0) [0|17592186044415] ""  PC

BO_ 2335108769 M2P_SUMDATA39__17: 8 MBMU
 SG_ M2P_SOE_Charge_B5 : 0|10@1+ (0.1,0) [0|102.3] "%"  PC
 SG_ M2P_SOE_Discharge_B5 : 10|10@1+ (0.1,0) [0|102.3] "%"  PC
 SG_ Reserved_17 : 20|44@1+ (1,0) [0|17592186044415] ""  PC

BO_ 2335108770 M2P_SUMDATA39__18: 8 MBMU
 SG_ M2P_SOE_Charge_B5 : 0|10@1+ (0.1,0) [0|102.3] "%"  PC
 SG_ M2P_SOE_Discharge_B5 : 10|10@1+ (0.1,0) [0|102.3] "%"  PC
 SG_ Reserved_18 : 20|44@1+ (1,0) [0|17592186044415] ""  PC

BO_ 2335108771 M2P_SUMDATA39__19: 8 MBMU
 SG_ M2P_SOE_Charge_B5 : 0|10@1+ (0.1,0) [0|102.3] "%"  PC
 SG_ M2P_SOE_Discharge_B5 : 10|10@1+ (0.1,0) [0|102.3] "%"  PC
 SG_ Reserved_19 : 20|44@1+ (1,0) [0|17592186044415] ""  PC

BO_ 2335108772 M2P_SUMDATA39__20: 8 MBMU
 SG_ M2P_SOE_Charge_B5 : 0|10@1+ (0.1,0) [0|102.3] "%"  PC
 SG_ M2P_SOE_Discharge_B5 : 10|10@1+ (0.1,0) [0|102.3] "%"  PC
 SG_ Reserved_20 : 20|44@1+ (1,0) [0|17592186044415] ""  PC

BO_ 2335108773 M2P_SUMDATA39__21: 8 MBMU
 SG_ M2P_SOE_Charge_B5 : 0|10@1+ (0.1,0) [0|102.3] "%"  PC
 SG_ M2P_SOE_Discharge_B5 : 10|10@1+ (0.1,0) [0|102.3] "%"  PC
 SG_ Reserved_21 : 20|44@1+ (1,0) [0|17592186044415] ""  PC

BO_ 2335108774 M2P_SUMDATA39__22: 8 MBMU
 SG_ M2P_SOE_Charge_B5 : 0|10@1+ (0.1,0) [0|102.3] "%"  PC
 SG_ M2P_SOE_Discharge_B5 : 10|10@1+ (0.1,0) [0|102.3] "%"  PC
 SG_ Reserved_22 : 20|44@1+ (1,0) [0|17592186044415] ""  PC

BO_ 2335108775 M2P_SUMDATA39__23: 8 MBMU
 SG_ M2P_SOE_Charge_B5 : 0|10@1+ (0.1,0) [0|102.3] "%"  PC
 SG_ M2P_SOE_Discharge_B5 : 10|10@1+ (0.1,0) [0|102.3] "%"  PC
 SG_ Reserved_23 : 20|44@1+ (1,0) [0|17592186044415] ""  PC

BO_ 2335108776 M2P_SUMDATA39__24: 8 MBMU
 SG_ M2P_SOE_Charge_B5 : 0|10@1+ (0.1,0) [0|102.3] "%"  PC
 SG_ M2P_SOE_Discharge_B5 : 10|10@1+ (0.1,0) [0|102.3] "%"  PC
 SG_ Reserved_24 : 20|44@1+ (1,0) [0|17592186044415] ""  PC

BO_ 2335108777 M2P_SUMDATA39__25: 8 MBMU
 SG_ M2P_SOE_Charge_B5 : 0|10@1+ (0.1,0) [0|102.3] "%"  PC
 SG_ M2P_SOE_Discharge_B5 : 10|10@1+ (0.1,0) [0|102.3] "%"  PC
 SG_ Reserved_25 : 20|44@1+ (1,0) [0|17592186044415] ""  PC

BO_ 2335108778 M2P_SUMDATA39__26: 8 MBMU
 SG_ M2P_SOE_Charge_B5 : 0|10@1+ (0.1,0) [0|102.3] "%"  PC
 SG_ M2P_SOE_Discharge_B5 : 10|10@1+ (0.1,0) [0|102.3] "%"  PC
 SG_ Reserved_26 : 20|44@1+ (1,0) [0|17592186044415] ""  PC

BO_ 2335108779 M2P_SUMDATA39__27: 8 MBMU
 SG_ M2P_SOE_Charge_B5 : 0|10@1+ (0.1,0) [0|102.3] "%"  PC
 SG_ M2P_SOE_Discharge_B5 : 10|10@1+ (0.1,0) [0|102.3] "%"  PC
 SG_ Reserved_27 : 20|44@1+ (1,0) [0|17592186044415] ""  PC

BO_ 2335108780 M2P_SUMDATA39__28: 8 MBMU
 SG_ M2P_SOE_Charge_B5 : 0|10@1+ (0.1,0) [0|102.3] "%"  PC
 SG_ M2P_SOE_Discharge_B5 : 10|10@1+ (0.1,0) [0|102.3] "%"  PC
 SG_ Reserved_28 : 20|44@1+ (1,0) [0|17592186044415] ""  PC

BO_ 2335108781 M2P_SUMDATA39__29: 8 MBMU
 SG_ M2P_SOE_Charge_B5 : 0|10@1+ (0.1,0) [0|102.3] "%"  PC
 SG_ M2P_SOE_Discharge_B5 : 10|10@1+ (0.1,0) [0|102.3] "%"  PC
 SG_ Reserved_29 : 20|44@1+ (1,0) [0|17592186044415] ""  PC

BO_ 2335108782 M2P_SUMDATA39__30: 8 MBMU
 SG_ M2P_SOE_Charge_B5 : 0|10@1+ (0.1,0) [0|102.3] "%"  PC
 SG_ M2P_SOE_Discharge_B5 : 10|10@1+ (0.1,0) [0|102.3] "%"  PC
 SG_ Reserved_30 : 20|44@1+ (1,0) [0|17592186044415] ""  PC

BO_ 2335108783 M2P_SUMDATA39__31: 8 MBMU
 SG_ M2P_SOE_Charge_B5 : 0|10@1+ (0.1,0) [0|102.3] "%"  PC
 SG_ M2P_SOE_Discharge_B5 : 10|10@1+ (0.1,0) [0|102.3] "%"  PC
 SG_ Reserved_31 : 20|44@1+ (1,0) [0|17592186044415] ""  PC

BO_ 2335174289 M2P_SUMDATA40__01: 8 MBMU
 SG_ M2P_Measure_Vol_B6_01 : 0|16@1+ (0.1,0) [0|6553.5] "V"  PC,SBMU
 SG_ M2P_Current_B6_01 : 16|16@1+ (1,-20000) [-20000|45535] "A"  PC,SBMU
 SG_ M2P_PermitMaxCharge_I_B6_01 : 32|16@1+ (1,-20000) [-20000|45535] "A"  PC
 SG_ M2P_PermitMaxDisCharge_I_B6_01 : 48|16@1+ (1,-20000) [-20000|45535] "A"  PC

BO_ 2335174290 M2P_SUMDATA40__02: 8 MBMU
 SG_ M2P_Measure_Vol_B6_02 : 0|16@1+ (0.1,0) [0|6553.5] "V"  PC,SBMU
 SG_ M2P_Current_B6_02 : 16|16@1+ (1,-20000) [-20000|45535] "A"  PC,SBMU
 SG_ M2P_PermitMaxCharge_I_B6_02 : 32|16@1+ (1,-20000) [-20000|45535] "A"  PC
 SG_ M2P_PermitMaxDisCharge_I_B6_02 : 48|16@1+ (1,-20000) [-20000|45535] "A"  PC

BO_ 2335174291 M2P_SUMDATA40__03: 8 MBMU
 SG_ M2P_Measure_Vol_B6_03 : 0|16@1+ (0.1,0) [0|6553.5] "V"  PC,SBMU
 SG_ M2P_Current_B6_03 : 16|16@1+ (1,-20000) [-20000|45535] "A"  PC,SBMU
 SG_ M2P_PermitMaxCharge_I_B6_03 : 32|16@1+ (1,-20000) [-20000|45535] "A"  PC
 SG_ M2P_PermitMaxDisCharge_I_B6_03 : 48|16@1+ (1,-20000) [-20000|45535] "A"  PC

BO_ 2335174292 M2P_SUMDATA40__04: 8 MBMU
 SG_ M2P_Measure_Vol_B6_04 : 0|16@1+ (0.1,0) [0|6553.5] "V"  PC,SBMU
 SG_ M2P_Current_B6_04 : 16|16@1+ (1,-20000) [-20000|45535] "A"  PC,SBMU
 SG_ M2P_PermitMaxCharge_I_B6_04 : 32|16@1+ (1,-20000) [-20000|45535] "A"  PC
 SG_ M2P_PermitMaxDisCharge_I_B6_04 : 48|16@1+ (1,-20000) [-20000|45535] "A"  PC

BO_ 2335174293 M2P_SUMDATA40__05: 8 MBMU
 SG_ M2P_Measure_Vol_B6_05 : 0|16@1+ (0.1,0) [0|6553.5] "V"  PC,SBMU
 SG_ M2P_Current_B6_05 : 16|16@1+ (1,-20000) [-20000|45535] "A"  PC,SBMU
 SG_ M2P_PermitMaxCharge_I_B6_05 : 32|16@1+ (1,-20000) [-20000|45535] "A"  PC
 SG_ M2P_PermitMaxDisCharge_I_B6_05 : 48|16@1+ (1,-20000) [-20000|45535] "A"  PC

BO_ 2335174294 M2P_SUMDATA40__06: 8 MBMU
 SG_ M2P_Measure_Vol_B6_06 : 0|16@1+ (0.1,0) [0|6553.5] "V"  PC,SBMU
 SG_ M2P_Current_B6_06 : 16|16@1+ (1,-20000) [-20000|45535] "A"  PC,SBMU
 SG_ M2P_PermitMaxCharge_I_B6_06 : 32|16@1+ (1,-20000) [-20000|45535] "A"  PC
 SG_ M2P_PermitMaxDisCharge_I_B6_06 : 48|16@1+ (1,-20000) [-20000|45535] "A"  PC

BO_ 2335174295 M2P_SUMDATA40__07: 8 MBMU
 SG_ M2P_Measure_Vol_B6_07 : 0|16@1+ (0.1,0) [0|6553.5] "V"  PC,SBMU
 SG_ M2P_Current_B6_07 : 16|16@1+ (1,-20000) [-20000|45535] "A"  PC,SBMU
 SG_ M2P_PermitMaxCharge_I_B6_07 : 32|16@1+ (1,-20000) [-20000|45535] "A"  PC
 SG_ M2P_PermitMaxDisCharge_I_B6_07 : 48|16@1+ (1,-20000) [-20000|45535] "A"  PC

BO_ 2335174296 M2P_SUMDATA40__08: 8 MBMU
 SG_ M2P_Measure_Vol_B6_08 : 0|16@1+ (0.1,0) [0|6553.5] "V"  PC,SBMU
 SG_ M2P_Current_B6_08 : 16|16@1+ (1,-20000) [-20000|45535] "A"  PC,SBMU
 SG_ M2P_PermitMaxCharge_I_B6_08 : 32|16@1+ (1,-20000) [-20000|45535] "A"  PC
 SG_ M2P_PermitMaxDisCharge_I_B6_08 : 48|16@1+ (1,-20000) [-20000|45535] "A"  PC

BO_ 2335174297 M2P_SUMDATA40__09: 8 MBMU
 SG_ M2P_Measure_Vol_B6_09 : 0|16@1+ (0.1,0) [0|6553.5] "V"  PC,SBMU
 SG_ M2P_Current_B6_09 : 16|16@1+ (1,-20000) [-20000|45535] "A"  PC,SBMU
 SG_ M2P_PermitMaxCharge_I_B6_09 : 32|16@1+ (1,-20000) [-20000|45535] "A"  PC
 SG_ M2P_PermitMaxDisCharge_I_B6_09 : 48|16@1+ (1,-20000) [-20000|45535] "A"  PC

BO_ 2335174298 M2P_SUMDATA40__10: 8 MBMU
 SG_ M2P_Measure_Vol_B6_10 : 0|16@1+ (0.1,0) [0|6553.5] "V"  PC,SBMU
 SG_ M2P_Current_B6_10 : 16|16@1+ (1,-20000) [-20000|45535] "A"  PC,SBMU
 SG_ M2P_PermitMaxCharge_I_B6_10 : 32|16@1+ (1,-20000) [-20000|45535] "A"  PC
 SG_ M2P_PermitMaxDisCharge_I_B6_10 : 48|16@1+ (1,-20000) [-20000|45535] "A"  PC

BO_ 2335174299 M2P_SUMDATA40__11: 8 MBMU
 SG_ M2P_Measure_Vol_B6_11 : 0|16@1+ (0.1,0) [0|6553.5] "V"  PC,SBMU
 SG_ M2P_Current_B6_11 : 16|16@1+ (1,-20000) [-20000|45535] "A"  PC,SBMU
 SG_ M2P_PermitMaxCharge_I_B6_11 : 32|16@1+ (1,-20000) [-20000|45535] "A"  PC
 SG_ M2P_PermitMaxDisCharge_I_B6_11 : 48|16@1+ (1,-20000) [-20000|45535] "A"  PC

BO_ 2335174300 M2P_SUMDATA40__12: 8 MBMU
 SG_ M2P_Measure_Vol_B6_12 : 0|16@1+ (0.1,0) [0|6553.5] "V"  PC,SBMU
 SG_ M2P_Current_B6_12 : 16|16@1+ (1,-20000) [-20000|45535] "A"  PC,SBMU
 SG_ M2P_PermitMaxCharge_I_B6_12 : 32|16@1+ (1,-20000) [-20000|45535] "A"  PC
 SG_ M2P_PermitMaxDisCharge_I_B6_12 : 48|16@1+ (1,-20000) [-20000|45535] "A"  PC

BO_ 2335174301 M2P_SUMDATA40__13: 8 MBMU
 SG_ M2P_Measure_Vol_B6_13 : 0|16@1+ (0.1,0) [0|6553.5] "V"  PC,SBMU
 SG_ M2P_Current_B6_13 : 16|16@1+ (1,-20000) [-20000|45535] "A"  PC,SBMU
 SG_ M2P_PermitMaxCharge_I_B6_13 : 32|16@1+ (1,-20000) [-20000|45535] "A"  PC
 SG_ M2P_PermitMaxDisCharge_I_B6_13 : 48|16@1+ (1,-20000) [-20000|45535] "A"  PC

BO_ 2335174302 M2P_SUMDATA40__14: 8 MBMU
 SG_ M2P_Measure_Vol_B6_14 : 0|16@1+ (0.1,0) [0|6553.5] "V"  PC,SBMU
 SG_ M2P_Current_B6_14 : 16|16@1+ (1,-20000) [-20000|45535] "A"  PC,SBMU
 SG_ M2P_PermitMaxCharge_I_B6_14 : 32|16@1+ (1,-20000) [-20000|45535] "A"  PC
 SG_ M2P_PermitMaxDisCharge_I_B6_14 : 48|16@1+ (1,-20000) [-20000|45535] "A"  PC

BO_ 2335174303 M2P_SUMDATA40__15: 8 MBMU
 SG_ M2P_Measure_Vol_B6_15 : 0|16@1+ (0.1,0) [0|6553.5] "V"  PC,SBMU
 SG_ M2P_Current_B6_15 : 16|16@1+ (1,-20000) [-20000|45535] "A"  PC,SBMU
 SG_ M2P_PermitMaxCharge_I_B6_15 : 32|16@1+ (1,-20000) [-20000|45535] "A"  PC
 SG_ M2P_PermitMaxDisCharge_I_B6_15 : 48|16@1+ (1,-20000) [-20000|45535] "A"  PC

BO_ 2335174304 M2P_SUMDATA40__16: 8 MBMU
 SG_ M2P_Measure_Vol_B6_16 : 0|16@1+ (0.1,0) [0|6553.5] "V"  PC,SBMU
 SG_ M2P_Current_B6_16 : 16|16@1+ (1,-20000) [-20000|45535] "A"  PC,SBMU
 SG_ M2P_PermitMaxCharge_I_B6_16 : 32|16@1+ (1,-20000) [-20000|45535] "A"  PC
 SG_ M2P_PermitMaxDisCharge_I_B6_16 : 48|16@1+ (1,-20000) [-20000|45535] "A"  PC

BO_ 2335174305 M2P_SUMDATA40__17: 8 MBMU
 SG_ M2P_Measure_Vol_B6_17 : 0|16@1+ (0.1,0) [0|6553.5] "V"  PC,SBMU
 SG_ M2P_Current_B6_17 : 16|16@1+ (1,-20000) [-20000|45535] "A"  PC,SBMU
 SG_ M2P_PermitMaxCharge_I_B6_17 : 32|16@1+ (1,-20000) [-20000|45535] "A"  PC
 SG_ M2P_PermitMaxDisCharge_I_B6_17 : 48|16@1+ (1,-20000) [-20000|45535] "A"  PC

BO_ 2335174306 M2P_SUMDATA40__18: 8 MBMU
 SG_ M2P_Measure_Vol_B6_18 : 0|16@1+ (0.1,0) [0|6553.5] "V"  PC,SBMU
 SG_ M2P_Current_B6_18 : 16|16@1+ (1,-20000) [-20000|45535] "A"  PC,SBMU
 SG_ M2P_PermitMaxCharge_I_B6_18 : 32|16@1+ (1,-20000) [-20000|45535] "A"  PC
 SG_ M2P_PermitMaxDisCharge_I_B6_18 : 48|16@1+ (1,-20000) [-20000|45535] "A"  PC

BO_ 2335174307 M2P_SUMDATA40__19: 8 MBMU
 SG_ M2P_Measure_Vol_B6_19 : 0|16@1+ (0.1,0) [0|6553.5] "V"  PC,SBMU
 SG_ M2P_Current_B6_19 : 16|16@1+ (1,-20000) [-20000|45535] "A"  PC,SBMU
 SG_ M2P_PermitMaxCharge_I_B6_19 : 32|16@1+ (1,-20000) [-20000|45535] "A"  PC
 SG_ M2P_PermitMaxDisCharge_I_B6_19 : 48|16@1+ (1,-20000) [-20000|45535] "A"  PC

BO_ 2335174308 M2P_SUMDATA40__20: 8 MBMU
 SG_ M2P_Measure_Vol_B6_20 : 0|16@1+ (0.1,0) [0|6553.5] "V"  PC,SBMU
 SG_ M2P_Current_B6_20 : 16|16@1+ (1,-20000) [-20000|45535] "A"  PC,SBMU
 SG_ M2P_PermitMaxCharge_I_B6_20 : 32|16@1+ (1,-20000) [-20000|45535] "A"  PC
 SG_ M2P_PermitMaxDisCharge_I_B6_20 : 48|16@1+ (1,-20000) [-20000|45535] "A"  PC

BO_ 2335174309 M2P_SUMDATA40__21: 8 MBMU
 SG_ M2P_Measure_Vol_B6_21 : 0|16@1+ (0.1,0) [0|6553.5] "V"  PC,SBMU
 SG_ M2P_Current_B6_21 : 16|16@1+ (1,-20000) [-20000|45535] "A"  PC,SBMU
 SG_ M2P_PermitMaxCharge_I_B6_21 : 32|16@1+ (1,-20000) [-20000|45535] "A"  PC
 SG_ M2P_PermitMaxDisCharge_I_B6_21 : 48|16@1+ (1,-20000) [-20000|45535] "A"  PC

BO_ 2335174310 M2P_SUMDATA40__22: 8 MBMU
 SG_ M2P_Measure_Vol_B6_22 : 0|16@1+ (0.1,0) [0|6553.5] "V"  PC,SBMU
 SG_ M2P_Current_B6_22 : 16|16@1+ (1,-20000) [-20000|45535] "A"  PC,SBMU
 SG_ M2P_PermitMaxCharge_I_B6_22 : 32|16@1+ (1,-20000) [-20000|45535] "A"  PC
 SG_ M2P_PermitMaxDisCharge_I_B6_22 : 48|16@1+ (1,-20000) [-20000|45535] "A"  PC

BO_ 2335174311 M2P_SUMDATA40__23: 8 MBMU
 SG_ M2P_Measure_Vol_B6_23 : 0|16@1+ (0.1,0) [0|6553.5] "V"  PC,SBMU
 SG_ M2P_Current_B6_23 : 16|16@1+ (1,-20000) [-20000|45535] "A"  PC,SBMU
 SG_ M2P_PermitMaxCharge_I_B6_23 : 32|16@1+ (1,-20000) [-20000|45535] "A"  PC
 SG_ M2P_PermitMaxDisCharge_I_B6_23 : 48|16@1+ (1,-20000) [-20000|45535] "A"  PC

BO_ 2335174312 M2P_SUMDATA40__24: 8 MBMU
 SG_ M2P_Measure_Vol_B6_24 : 0|16@1+ (0.1,0) [0|6553.5] "V"  PC,SBMU
 SG_ M2P_Current_B6_24 : 16|16@1+ (1,-20000) [-20000|45535] "A"  PC,SBMU
 SG_ M2P_PermitMaxCharge_I_B6_24 : 32|16@1+ (1,-20000) [-20000|45535] "A"  PC
 SG_ M2P_PermitMaxDisCharge_I_B6_24 : 48|16@1+ (1,-20000) [-20000|45535] "A"  PC

BO_ 2335174313 M2P_SUMDATA40__25: 8 MBMU
 SG_ M2P_Measure_Vol_B6_25 : 0|16@1+ (0.1,0) [0|6553.5] "V"  PC,SBMU
 SG_ M2P_Current_B6_25 : 16|16@1+ (1,-20000) [-20000|45535] "A"  PC,SBMU
 SG_ M2P_PermitMaxCharge_I_B6_25 : 32|16@1+ (1,-20000) [-20000|45535] "A"  PC
 SG_ M2P_PermitMaxDisCharge_I_B6_25 : 48|16@1+ (1,-20000) [-20000|45535] "A"  PC

BO_ 2335174314 M2P_SUMDATA40__26: 8 MBMU
 SG_ M2P_Measure_Vol_B6_26 : 0|16@1+ (0.1,0) [0|6553.5] "V"  PC,SBMU
 SG_ M2P_Current_B6_26 : 16|16@1+ (1,-20000) [-20000|45535] "A"  PC,SBMU
 SG_ M2P_PermitMaxCharge_I_B6_26 : 32|16@1+ (1,-20000) [-20000|45535] "A"  PC
 SG_ M2P_PermitMaxDisCharge_I_B6_26 : 48|16@1+ (1,-20000) [-20000|45535] "A"  PC

BO_ 2335174315 M2P_SUMDATA40__27: 8 MBMU
 SG_ M2P_Measure_Vol_B6_27 : 0|16@1+ (0.1,0) [0|6553.5] "V"  PC,SBMU
 SG_ M2P_Current_B6_27 : 16|16@1+ (1,-20000) [-20000|45535] "A"  PC,SBMU
 SG_ M2P_PermitMaxCharge_I_B6_27 : 32|16@1+ (1,-20000) [-20000|45535] "A"  PC
 SG_ M2P_PermitMaxDisCharge_I_B6_27 : 48|16@1+ (1,-20000) [-20000|45535] "A"  PC

BO_ 2335174316 M2P_SUMDATA40__28: 8 MBMU
 SG_ M2P_Measure_Vol_B6_28 : 0|16@1+ (0.1,0) [0|6553.5] "V"  PC,SBMU
 SG_ M2P_Current_B6_28 : 16|16@1+ (1,-20000) [-20000|45535] "A"  PC,SBMU
 SG_ M2P_PermitMaxCharge_I_B6_28 : 32|16@1+ (1,-20000) [-20000|45535] "A"  PC
 SG_ M2P_PermitMaxDisCharge_I_B6_28 : 48|16@1+ (1,-20000) [-20000|45535] "A"  PC

BO_ 2335174317 M2P_SUMDATA40__29: 8 MBMU
 SG_ M2P_Measure_Vol_B6_29 : 0|16@1+ (0.1,0) [0|6553.5] "V"  PC,SBMU
 SG_ M2P_Current_B6_29 : 16|16@1+ (1,-20000) [-20000|45535] "A"  PC,SBMU
 SG_ M2P_PermitMaxCharge_I_B6_29 : 32|16@1+ (1,-20000) [-20000|45535] "A"  PC
 SG_ M2P_PermitMaxDisCharge_I_B6_29 : 48|16@1+ (1,-20000) [-20000|45535] "A"  PC

BO_ 2335174318 M2P_SUMDATA40__30: 8 MBMU
 SG_ M2P_Measure_Vol_B6_30 : 0|16@1+ (0.1,0) [0|6553.5] "V"  PC,SBMU
 SG_ M2P_Current_B6_30 : 16|16@1+ (1,-20000) [-20000|45535] "A"  PC,SBMU
 SG_ M2P_PermitMaxCharge_I_B6_30 : 32|16@1+ (1,-20000) [-20000|45535] "A"  PC
 SG_ M2P_PermitMaxDisCharge_I_B6_30 : 48|16@1+ (1,-20000) [-20000|45535] "A"  PC

BO_ 2335174319 M2P_SUMDATA40__31: 8 MBMU
 SG_ M2P_Measure_Vol_B6_31 : 0|16@1+ (0.1,0) [0|6553.5] "V"  PC,SBMU
 SG_ M2P_Current_B6_31 : 16|16@1+ (1,-20000) [-20000|45535] "A"  PC,SBMU
 SG_ M2P_PermitMaxCharge_I_B6_31 : 32|16@1+ (1,-20000) [-20000|45535] "A"  PC
 SG_ M2P_PermitMaxDisCharge_I_B6_31 : 48|16@1+ (1,-20000) [-20000|45535] "A"  PC

BO_ 2335239825 M2P_SUMDATA41__01: 8 MBMU
 SG_ M2P_PermitMaxVolt_B6_01 : 0|16@1+ (0.1,0) [0|6553.5] "V"  PC
 SG_ M2P_PermitMinVolt_B6_01 : 16|16@1+ (0.1,0) [0|6553.5] "V"  PC
 SG_ M2P_PermitMaxPow_Chg_B6_01 : 32|16@1+ (1,-20000) [-20000|45535] "Kw"  PC
 SG_ M2P_PermitMaxPow_DisChg_B6_01 : 48|16@1+ (1,-20000) [-20000|45535] "Kw"  PC

BO_ 2335239826 M2P_SUMDATA41__02: 8 MBMU
 SG_ M2P_PermitMaxVolt_B6_02 : 0|16@1+ (0.1,0) [0|6553.5] "V"  PC
 SG_ M2P_PermitMinVolt_B6_02 : 16|16@1+ (0.1,0) [0|6553.5] "V"  PC
 SG_ M2P_PermitMaxPow_Chg_B6_02 : 32|16@1+ (1,-20000) [-20000|45535] "Kw"  PC
 SG_ M2P_PermitMaxPow_DisChg_B6_02 : 48|16@1+ (1,-20000) [-20000|45535] "Kw"  PC

BO_ 2335239827 M2P_SUMDATA41__03: 8 MBMU
 SG_ M2P_PermitMaxVolt_B6_03 : 0|16@1+ (0.1,0) [0|6553.5] "V"  PC
 SG_ M2P_PermitMinVolt_B6_03 : 16|16@1+ (0.1,0) [0|6553.5] "V"  PC
 SG_ M2P_PermitMaxPow_Chg_B6_03 : 32|16@1+ (1,-20000) [-20000|45535] "Kw"  PC
 SG_ M2P_PermitMaxPow_DisChg_B6_03 : 48|16@1+ (1,-20000) [-20000|45535] "Kw"  PC

BO_ 2335239828 M2P_SUMDATA41__04: 8 MBMU
 SG_ M2P_PermitMaxVolt_B6_04 : 0|16@1+ (0.1,0) [0|6553.5] "V"  PC
 SG_ M2P_PermitMinVolt_B6_04 : 16|16@1+ (0.1,0) [0|6553.5] "V"  PC
 SG_ M2P_PermitMaxPow_Chg_B6_04 : 32|16@1+ (1,-20000) [-20000|45535] "Kw"  PC
 SG_ M2P_PermitMaxPow_DisChg_B6_04 : 48|16@1+ (1,-20000) [-20000|45535] "Kw"  PC

BO_ 2335239829 M2P_SUMDATA41__05: 8 MBMU
 SG_ M2P_PermitMaxVolt_B6_05 : 0|16@1+ (0.1,0) [0|6553.5] "V"  PC
 SG_ M2P_PermitMinVolt_B6_05 : 16|16@1+ (0.1,0) [0|6553.5] "V"  PC
 SG_ M2P_PermitMaxPow_Chg_B6_05 : 32|16@1+ (1,-20000) [-20000|45535] "Kw"  PC
 SG_ M2P_PermitMaxPow_DisChg_B6_05 : 48|16@1+ (1,-20000) [-20000|45535] "Kw"  PC

BO_ 2335239830 M2P_SUMDATA41__06: 8 MBMU
 SG_ M2P_PermitMaxVolt_B6_06 : 0|16@1+ (0.1,0) [0|6553.5] "V"  PC
 SG_ M2P_PermitMinVolt_B6_06 : 16|16@1+ (0.1,0) [0|6553.5] "V"  PC
 SG_ M2P_PermitMaxPow_Chg_B6_06 : 32|16@1+ (1,-20000) [-20000|45535] "Kw"  PC
 SG_ M2P_PermitMaxPow_DisChg_B6_06 : 48|16@1+ (1,-20000) [-20000|45535] "Kw"  PC

BO_ 2335239831 M2P_SUMDATA41__07: 8 MBMU
 SG_ M2P_PermitMaxVolt_B6_07 : 0|16@1+ (0.1,0) [0|6553.5] "V"  PC
 SG_ M2P_PermitMinVolt_B6_07 : 16|16@1+ (0.1,0) [0|6553.5] "V"  PC
 SG_ M2P_PermitMaxPow_Chg_B6_07 : 32|16@1+ (1,-20000) [-20000|45535] "Kw"  PC
 SG_ M2P_PermitMaxPow_DisChg_B6_07 : 48|16@1+ (1,-20000) [-20000|45535] "Kw"  PC

BO_ 2335239832 M2P_SUMDATA41__08: 8 MBMU
 SG_ M2P_PermitMaxVolt_B6_08 : 0|16@1+ (0.1,0) [0|6553.5] "V"  PC
 SG_ M2P_PermitMinVolt_B6_08 : 16|16@1+ (0.1,0) [0|6553.5] "V"  PC
 SG_ M2P_PermitMaxPow_Chg_B6_08 : 32|16@1+ (1,-20000) [-20000|45535] "Kw"  PC
 SG_ M2P_PermitMaxPow_DisChg_B6_08 : 48|16@1+ (1,-20000) [-20000|45535] "Kw"  PC

BO_ 2335239833 M2P_SUMDATA41__09: 8 MBMU
 SG_ M2P_PermitMaxVolt_B6_09 : 0|16@1+ (0.1,0) [0|6553.5] "V"  PC
 SG_ M2P_PermitMinVolt_B6_09 : 16|16@1+ (0.1,0) [0|6553.5] "V"  PC
 SG_ M2P_PermitMaxPow_Chg_B6_09 : 32|16@1+ (1,-20000) [-20000|45535] "Kw"  PC
 SG_ M2P_PermitMaxPow_DisChg_B6_09 : 48|16@1+ (1,-20000) [-20000|45535] "Kw"  PC

BO_ 2335239834 M2P_SUMDATA41__10: 8 MBMU
 SG_ M2P_PermitMaxVolt_B6_10 : 0|16@1+ (0.1,0) [0|6553.5] "V"  PC
 SG_ M2P_PermitMinVolt_B6_10 : 16|16@1+ (0.1,0) [0|6553.5] "V"  PC
 SG_ M2P_PermitMaxPow_Chg_B6_10 : 32|16@1+ (1,-20000) [-20000|45535] "Kw"  PC
 SG_ M2P_PermitMaxPow_DisChg_B6_10 : 48|16@1+ (1,-20000) [-20000|45535] "Kw"  PC

BO_ 2335239835 M2P_SUMDATA41__11: 8 MBMU
 SG_ M2P_PermitMaxVolt_B6_11 : 0|16@1+ (0.1,0) [0|6553.5] "V"  PC
 SG_ M2P_PermitMinVolt_B6_11 : 16|16@1+ (0.1,0) [0|6553.5] "V"  PC
 SG_ M2P_PermitMaxPow_Chg_B6_11 : 32|16@1+ (1,-20000) [-20000|45535] "Kw"  PC
 SG_ M2P_PermitMaxPow_DisChg_B6_11 : 48|16@1+ (1,-20000) [-20000|45535] "Kw"  PC

BO_ 2335239836 M2P_SUMDATA41__12: 8 MBMU
 SG_ M2P_PermitMaxVolt_B6_12 : 0|16@1+ (0.1,0) [0|6553.5] "V"  PC
 SG_ M2P_PermitMinVolt_B6_12 : 16|16@1+ (0.1,0) [0|6553.5] "V"  PC
 SG_ M2P_PermitMaxPow_Chg_B6_12 : 32|16@1+ (1,-20000) [-20000|45535] "Kw"  PC
 SG_ M2P_PermitMaxPow_DisChg_B6_12 : 48|16@1+ (1,-20000) [-20000|45535] "Kw"  PC

BO_ 2335239837 M2P_SUMDATA41__13: 8 MBMU
 SG_ M2P_PermitMaxVolt_B6_13 : 0|16@1+ (0.1,0) [0|6553.5] "V"  PC
 SG_ M2P_PermitMinVolt_B6_13 : 16|16@1+ (0.1,0) [0|6553.5] "V"  PC
 SG_ M2P_PermitMaxPow_Chg_B6_13 : 32|16@1+ (1,-20000) [-20000|45535] "Kw"  PC
 SG_ M2P_PermitMaxPow_DisChg_B6_13 : 48|16@1+ (1,-20000) [-20000|45535] "Kw"  PC

BO_ 2335239838 M2P_SUMDATA41__14: 8 MBMU
 SG_ M2P_PermitMaxVolt_B6_14 : 0|16@1+ (0.1,0) [0|6553.5] "V"  PC
 SG_ M2P_PermitMinVolt_B6_14 : 16|16@1+ (0.1,0) [0|6553.5] "V"  PC
 SG_ M2P_PermitMaxPow_Chg_B6_14 : 32|16@1+ (1,-20000) [-20000|45535] "Kw"  PC
 SG_ M2P_PermitMaxPow_DisChg_B6_14 : 48|16@1+ (1,-20000) [-20000|45535] "Kw"  PC

BO_ 2335239839 M2P_SUMDATA41__15: 8 MBMU
 SG_ M2P_PermitMaxVolt_B6_15 : 0|16@1+ (0.1,0) [0|6553.5] "V"  PC
 SG_ M2P_PermitMinVolt_B6_15 : 16|16@1+ (0.1,0) [0|6553.5] "V"  PC
 SG_ M2P_PermitMaxPow_Chg_B6_15 : 32|16@1+ (1,-20000) [-20000|45535] "Kw"  PC
 SG_ M2P_PermitMaxPow_DisChg_B6_15 : 48|16@1+ (1,-20000) [-20000|45535] "Kw"  PC

BO_ 2335239840 M2P_SUMDATA41__16: 8 MBMU
 SG_ M2P_PermitMaxVolt_B6_16 : 0|16@1+ (0.1,0) [0|6553.5] "V"  PC
 SG_ M2P_PermitMinVolt_B6_16 : 16|16@1+ (0.1,0) [0|6553.5] "V"  PC
 SG_ M2P_PermitMaxPow_Chg_B6_16 : 32|16@1+ (1,-20000) [-20000|45535] "Kw"  PC
 SG_ M2P_PermitMaxPow_DisChg_B6_16 : 48|16@1+ (1,-20000) [-20000|45535] "Kw"  PC

BO_ 2335239841 M2P_SUMDATA41__17: 8 MBMU
 SG_ M2P_PermitMaxVolt_B6_17 : 0|16@1+ (0.1,0) [0|6553.5] "V"  PC
 SG_ M2P_PermitMinVolt_B6_17 : 16|16@1+ (0.1,0) [0|6553.5] "V"  PC
 SG_ M2P_PermitMaxPow_Chg_B6_17 : 32|16@1+ (1,-20000) [-20000|45535] "Kw"  PC
 SG_ M2P_PermitMaxPow_DisChg_B6_17 : 48|16@1+ (1,-20000) [-20000|45535] "Kw"  PC

BO_ 2335239842 M2P_SUMDATA41__18: 8 MBMU
 SG_ M2P_PermitMaxVolt_B6_18 : 0|16@1+ (0.1,0) [0|6553.5] "V"  PC
 SG_ M2P_PermitMinVolt_B6_18 : 16|16@1+ (0.1,0) [0|6553.5] "V"  PC
 SG_ M2P_PermitMaxPow_Chg_B6_18 : 32|16@1+ (1,-20000) [-20000|45535] "Kw"  PC
 SG_ M2P_PermitMaxPow_DisChg_B6_18 : 48|16@1+ (1,-20000) [-20000|45535] "Kw"  PC

BO_ 2335239843 M2P_SUMDATA41__19: 8 MBMU
 SG_ M2P_PermitMaxVolt_B6_19 : 0|16@1+ (0.1,0) [0|6553.5] "V"  PC
 SG_ M2P_PermitMinVolt_B6_19 : 16|16@1+ (0.1,0) [0|6553.5] "V"  PC
 SG_ M2P_PermitMaxPow_Chg_B6_19 : 32|16@1+ (1,-20000) [-20000|45535] "Kw"  PC
 SG_ M2P_PermitMaxPow_DisChg_B6_19 : 48|16@1+ (1,-20000) [-20000|45535] "Kw"  PC

BO_ 2335239844 M2P_SUMDATA41__20: 8 MBMU
 SG_ M2P_PermitMaxVolt_B6_20 : 0|16@1+ (0.1,0) [0|6553.5] "V"  PC
 SG_ M2P_PermitMinVolt_B6_20 : 16|16@1+ (0.1,0) [0|6553.5] "V"  PC
 SG_ M2P_PermitMaxPow_Chg_B6_20 : 32|16@1+ (1,-20000) [-20000|45535] "Kw"  PC
 SG_ M2P_PermitMaxPow_DisChg_B6_20 : 48|16@1+ (1,-20000) [-20000|45535] "Kw"  PC

BO_ 2335239845 M2P_SUMDATA41__21: 8 MBMU
 SG_ M2P_PermitMaxVolt_B6_21 : 0|16@1+ (0.1,0) [0|6553.5] "V"  PC
 SG_ M2P_PermitMinVolt_B6_21 : 16|16@1+ (0.1,0) [0|6553.5] "V"  PC
 SG_ M2P_PermitMaxPow_Chg_B6_21 : 32|16@1+ (1,-20000) [-20000|45535] "Kw"  PC
 SG_ M2P_PermitMaxPow_DisChg_B6_21 : 48|16@1+ (1,-20000) [-20000|45535] "Kw"  PC

BO_ 2335239846 M2P_SUMDATA41__22: 8 MBMU
 SG_ M2P_PermitMaxVolt_B6_22 : 0|16@1+ (0.1,0) [0|6553.5] "V"  PC
 SG_ M2P_PermitMinVolt_B6_22 : 16|16@1+ (0.1,0) [0|6553.5] "V"  PC
 SG_ M2P_PermitMaxPow_Chg_B6_22 : 32|16@1+ (1,-20000) [-20000|45535] "Kw"  PC
 SG_ M2P_PermitMaxPow_DisChg_B6_22 : 48|16@1+ (1,-20000) [-20000|45535] "Kw"  PC

BO_ 2335239847 M2P_SUMDATA41__23: 8 MBMU
 SG_ M2P_PermitMaxVolt_B6_23 : 0|16@1+ (0.1,0) [0|6553.5] "V"  PC
 SG_ M2P_PermitMinVolt_B6_23 : 16|16@1+ (0.1,0) [0|6553.5] "V"  PC
 SG_ M2P_PermitMaxPow_Chg_B6_23 : 32|16@1+ (1,-20000) [-20000|45535] "Kw"  PC
 SG_ M2P_PermitMaxPow_DisChg_B6_23 : 48|16@1+ (1,-20000) [-20000|45535] "Kw"  PC

BO_ 2335239848 M2P_SUMDATA41__24: 8 MBMU
 SG_ M2P_PermitMaxVolt_B6_24 : 0|16@1+ (0.1,0) [0|6553.5] "V"  PC
 SG_ M2P_PermitMinVolt_B6_24 : 16|16@1+ (0.1,0) [0|6553.5] "V"  PC
 SG_ M2P_PermitMaxPow_Chg_B6_24 : 32|16@1+ (1,-20000) [-20000|45535] "Kw"  PC
 SG_ M2P_PermitMaxPow_DisChg_B6_24 : 48|16@1+ (1,-20000) [-20000|45535] "Kw"  PC

BO_ 2335239849 M2P_SUMDATA41__25: 8 MBMU
 SG_ M2P_PermitMaxVolt_B6_25 : 0|16@1+ (0.1,0) [0|6553.5] "V"  PC
 SG_ M2P_PermitMinVolt_B6_25 : 16|16@1+ (0.1,0) [0|6553.5] "V"  PC
 SG_ M2P_PermitMaxPow_Chg_B6_25 : 32|16@1+ (1,-20000) [-20000|45535] "Kw"  PC
 SG_ M2P_PermitMaxPow_DisChg_B6_25 : 48|16@1+ (1,-20000) [-20000|45535] "Kw"  PC

BO_ 2335239850 M2P_SUMDATA41__26: 8 MBMU
 SG_ M2P_PermitMaxVolt_B6_26 : 0|16@1+ (0.1,0) [0|6553.5] "V"  PC
 SG_ M2P_PermitMinVolt_B6_26 : 16|16@1+ (0.1,0) [0|6553.5] "V"  PC
 SG_ M2P_PermitMaxPow_Chg_B6_26 : 32|16@1+ (1,-20000) [-20000|45535] "Kw"  PC
 SG_ M2P_PermitMaxPow_DisChg_B6_26 : 48|16@1+ (1,-20000) [-20000|45535] "Kw"  PC

BO_ 2335239851 M2P_SUMDATA41__27: 8 MBMU
 SG_ M2P_PermitMaxVolt_B6_27 : 0|16@1+ (0.1,0) [0|6553.5] "V"  PC
 SG_ M2P_PermitMinVolt_B6_27 : 16|16@1+ (0.1,0) [0|6553.5] "V"  PC
 SG_ M2P_PermitMaxPow_Chg_B6_27 : 32|16@1+ (1,-20000) [-20000|45535] "Kw"  PC
 SG_ M2P_PermitMaxPow_DisChg_B6_27 : 48|16@1+ (1,-20000) [-20000|45535] "Kw"  PC

BO_ 2335239852 M2P_SUMDATA41__28: 8 MBMU
 SG_ M2P_PermitMaxVolt_B6_28 : 0|16@1+ (0.1,0) [0|6553.5] "V"  PC
 SG_ M2P_PermitMinVolt_B6_28 : 16|16@1+ (0.1,0) [0|6553.5] "V"  PC
 SG_ M2P_PermitMaxPow_Chg_B6_28 : 32|16@1+ (1,-20000) [-20000|45535] "Kw"  PC
 SG_ M2P_PermitMaxPow_DisChg_B6_28 : 48|16@1+ (1,-20000) [-20000|45535] "Kw"  PC

BO_ 2335239853 M2P_SUMDATA41__29: 8 MBMU
 SG_ M2P_PermitMaxVolt_B6_29 : 0|16@1+ (0.1,0) [0|6553.5] "V"  PC
 SG_ M2P_PermitMinVolt_B6_29 : 16|16@1+ (0.1,0) [0|6553.5] "V"  PC
 SG_ M2P_PermitMaxPow_Chg_B6_29 : 32|16@1+ (1,-20000) [-20000|45535] "Kw"  PC
 SG_ M2P_PermitMaxPow_DisChg_B6_29 : 48|16@1+ (1,-20000) [-20000|45535] "Kw"  PC

BO_ 2335239854 M2P_SUMDATA41__30: 8 MBMU
 SG_ M2P_PermitMaxVolt_B6_30 : 0|16@1+ (0.1,0) [0|6553.5] "V"  PC
 SG_ M2P_PermitMinVolt_B6_30 : 16|16@1+ (0.1,0) [0|6553.5] "V"  PC
 SG_ M2P_PermitMaxPow_Chg_B6_30 : 32|16@1+ (1,-20000) [-20000|45535] "Kw"  PC
 SG_ M2P_PermitMaxPow_DisChg_B6_30 : 48|16@1+ (1,-20000) [-20000|45535] "Kw"  PC

BO_ 2335239855 M2P_SUMDATA41__31: 8 MBMU
 SG_ M2P_PermitMaxVolt_B6_31 : 0|16@1+ (0.1,0) [0|6553.5] "V"  PC
 SG_ M2P_PermitMinVolt_B6_31 : 16|16@1+ (0.1,0) [0|6553.5] "V"  PC
 SG_ M2P_PermitMaxPow_Chg_B6_31 : 32|16@1+ (1,-20000) [-20000|45535] "Kw"  PC
 SG_ M2P_PermitMaxPow_DisChg_B6_31 : 48|16@1+ (1,-20000) [-20000|45535] "Kw"  PC

BO_ 2335305361 M2P_SUMDATA42__01: 8 MBMU
 SG_ M2P_Power_B6_01 : 0|16@1+ (1,-20000) [-20000|45535] "Kw"  PC
 SG_ M2P_SysremEngy_Chg_B6_01 : 16|16@1+ (1,0) [0|65535] "Kwh"  PC
 SG_ M2P_SysremEngy_DisChg_B6_01 : 32|16@1+ (1,0) [0|65535] "Kwh"  PC
 SG_ M2P_SysMaxVolt_B6_01 : 48|16@1+ (1,0) [0|65535] "mv"  PC

BO_ 2335305362 M2P_SUMDATA42__02: 8 MBMU
 SG_ M2P_Power_B6_02 : 0|16@1+ (1,-20000) [-20000|45535] "Kw"  PC
 SG_ M2P_SysremEngy_Chg_B6_02 : 16|16@1+ (1,0) [0|65535] "Kwh"  PC
 SG_ M2P_SysremEngy_DisChg_B6_02 : 32|16@1+ (1,0) [0|65535] "Kwh"  PC
 SG_ M2P_SysMaxVolt_B6_02 : 48|16@1+ (1,0) [0|65535] "mv"  PC

BO_ 2335305363 M2P_SUMDATA42__03: 8 MBMU
 SG_ M2P_Power_B6_03 : 0|16@1+ (1,-20000) [-20000|45535] "Kw"  PC
 SG_ M2P_SysremEngy_Chg_B6_03 : 16|16@1+ (1,0) [0|65535] "Kwh"  PC
 SG_ M2P_SysremEngy_DisChg_B6_03 : 32|16@1+ (1,0) [0|65535] "Kwh"  PC
 SG_ M2P_SysMaxVolt_B6_03 : 48|16@1+ (1,0) [0|65535] "mv"  PC

BO_ 2335305364 M2P_SUMDATA42__04: 8 MBMU
 SG_ M2P_Power_B6_04 : 0|16@1+ (1,-20000) [-20000|45535] "Kw"  PC
 SG_ M2P_SysremEngy_Chg_B6_04 : 16|16@1+ (1,0) [0|65535] "Kwh"  PC
 SG_ M2P_SysremEngy_DisChg_B6_04 : 32|16@1+ (1,0) [0|65535] "Kwh"  PC
 SG_ M2P_SysMaxVolt_B6_04 : 48|16@1+ (1,0) [0|65535] "mv"  PC

BO_ 2335305365 M2P_SUMDATA42__05: 8 MBMU
 SG_ M2P_Power_B6_05 : 0|16@1+ (1,-20000) [-20000|45535] "Kw"  PC
 SG_ M2P_SysremEngy_Chg_B6_05 : 16|16@1+ (1,0) [0|65535] "Kwh"  PC
 SG_ M2P_SysremEngy_DisChg_B6_05 : 32|16@1+ (1,0) [0|65535] "Kwh"  PC
 SG_ M2P_SysMaxVolt_B6_05 : 48|16@1+ (1,0) [0|65535] "mv"  PC

BO_ 2335305366 M2P_SUMDATA42__06: 8 MBMU
 SG_ M2P_Power_B6_06 : 0|16@1+ (1,-20000) [-20000|45535] "Kw"  PC
 SG_ M2P_SysremEngy_Chg_B6_06 : 16|16@1+ (1,0) [0|65535] "Kwh"  PC
 SG_ M2P_SysremEngy_DisChg_B6_06 : 32|16@1+ (1,0) [0|65535] "Kwh"  PC
 SG_ M2P_SysMaxVolt_B6_06 : 48|16@1+ (1,0) [0|65535] "mv"  PC

BO_ 2335305367 M2P_SUMDATA42__07: 8 MBMU
 SG_ M2P_Power_B6_07 : 0|16@1+ (1,-20000) [-20000|45535] "Kw"  PC
 SG_ M2P_SysremEngy_Chg_B6_07 : 16|16@1+ (1,0) [0|65535] "Kwh"  PC
 SG_ M2P_SysremEngy_DisChg_B6_07 : 32|16@1+ (1,0) [0|65535] "Kwh"  PC
 SG_ M2P_SysMaxVolt_B6_07 : 48|16@1+ (1,0) [0|65535] "mv"  PC

BO_ 2335305368 M2P_SUMDATA42__08: 8 MBMU
 SG_ M2P_Power_B6_08 : 0|16@1+ (1,-20000) [-20000|45535] "Kw"  PC
 SG_ M2P_SysremEngy_Chg_B6_08 : 16|16@1+ (1,0) [0|65535] "Kwh"  PC
 SG_ M2P_SysremEngy_DisChg_B6_08 : 32|16@1+ (1,0) [0|65535] "Kwh"  PC
 SG_ M2P_SysMaxVolt_B6_08 : 48|16@1+ (1,0) [0|65535] "mv"  PC

BO_ 2335305369 M2P_SUMDATA42__09: 8 MBMU
 SG_ M2P_Power_B6_09 : 0|16@1+ (1,-20000) [-20000|45535] "Kw"  PC
 SG_ M2P_SysremEngy_Chg_B6_09 : 16|16@1+ (1,0) [0|65535] "Kwh"  PC
 SG_ M2P_SysremEngy_DisChg_B6_09 : 32|16@1+ (1,0) [0|65535] "Kwh"  PC
 SG_ M2P_SysMaxVolt_B6_09 : 48|16@1+ (1,0) [0|65535] "mv"  PC

BO_ 2335305370 M2P_SUMDATA42__10: 8 MBMU
 SG_ M2P_Power_B6_10 : 0|16@1+ (1,-20000) [-20000|45535] "Kw"  PC
 SG_ M2P_SysremEngy_Chg_B6_10 : 16|16@1+ (1,0) [0|65535] "Kwh"  PC
 SG_ M2P_SysremEngy_DisChg_B6_10 : 32|16@1+ (1,0) [0|65535] "Kwh"  PC
 SG_ M2P_SysMaxVolt_B6_10 : 48|16@1+ (1,0) [0|65535] "mv"  PC

BO_ 2335305371 M2P_SUMDATA42__11: 8 MBMU
 SG_ M2P_Power_B6_11 : 0|16@1+ (1,-20000) [-20000|45535] "Kw"  PC
 SG_ M2P_SysremEngy_Chg_B6_11 : 16|16@1+ (1,0) [0|65535] "Kwh"  PC
 SG_ M2P_SysremEngy_DisChg_B6_11 : 32|16@1+ (1,0) [0|65535] "Kwh"  PC
 SG_ M2P_SysMaxVolt_B6_11 : 48|16@1+ (1,0) [0|65535] "mv"  PC

BO_ 2335305372 M2P_SUMDATA42__12: 8 MBMU
 SG_ M2P_Power_B6_12 : 0|16@1+ (1,-20000) [-20000|45535] "Kw"  PC
 SG_ M2P_SysremEngy_Chg_B6_12 : 16|16@1+ (1,0) [0|65535] "Kwh"  PC
 SG_ M2P_SysremEngy_DisChg_B6_12 : 32|16@1+ (1,0) [0|65535] "Kwh"  PC
 SG_ M2P_SysMaxVolt_B6_12 : 48|16@1+ (1,0) [0|65535] "mv"  PC

BO_ 2335305373 M2P_SUMDATA42__13: 8 MBMU
 SG_ M2P_Power_B6_13 : 0|16@1+ (1,-20000) [-20000|45535] "Kw"  PC
 SG_ M2P_SysremEngy_Chg_B6_13 : 16|16@1+ (1,0) [0|65535] "Kwh"  PC
 SG_ M2P_SysremEngy_DisChg_B6_13 : 32|16@1+ (1,0) [0|65535] "Kwh"  PC
 SG_ M2P_SysMaxVolt_B6_13 : 48|16@1+ (1,0) [0|65535] "mv"  PC

BO_ 2335305374 M2P_SUMDATA42__14: 8 MBMU
 SG_ M2P_Power_B6_14 : 0|16@1+ (1,-20000) [-20000|45535] "Kw"  PC
 SG_ M2P_SysremEngy_Chg_B6_14 : 16|16@1+ (1,0) [0|65535] "Kwh"  PC
 SG_ M2P_SysremEngy_DisChg_B6_14 : 32|16@1+ (1,0) [0|65535] "Kwh"  PC
 SG_ M2P_SysMaxVolt_B6_14 : 48|16@1+ (1,0) [0|65535] "mv"  PC

BO_ 2335305375 M2P_SUMDATA42__15: 8 MBMU
 SG_ M2P_Power_B6_15 : 0|16@1+ (1,-20000) [-20000|45535] "Kw"  PC
 SG_ M2P_SysremEngy_Chg_B6_15 : 16|16@1+ (1,0) [0|65535] "Kwh"  PC
 SG_ M2P_SysremEngy_DisChg_B6_15 : 32|16@1+ (1,0) [0|65535] "Kwh"  PC
 SG_ M2P_SysMaxVolt_B6_15 : 48|16@1+ (1,0) [0|65535] "mv"  PC

BO_ 2335305376 M2P_SUMDATA42__16: 8 MBMU
 SG_ M2P_Power_B6_16 : 0|16@1+ (1,-20000) [-20000|45535] "Kw"  PC
 SG_ M2P_SysremEngy_Chg_B6_16 : 16|16@1+ (1,0) [0|65535] "Kwh"  PC
 SG_ M2P_SysremEngy_DisChg_B6_16 : 32|16@1+ (1,0) [0|65535] "Kwh"  PC
 SG_ M2P_SysMaxVolt_B6_16 : 48|16@1+ (1,0) [0|65535] "mv"  PC

BO_ 2335305377 M2P_SUMDATA42__17: 8 MBMU
 SG_ M2P_Power_B6_17 : 0|16@1+ (1,-20000) [-20000|45535] "Kw"  PC
 SG_ M2P_SysremEngy_Chg_B6_17 : 16|16@1+ (1,0) [0|65535] "Kwh"  PC
 SG_ M2P_SysremEngy_DisChg_B6_17 : 32|16@1+ (1,0) [0|65535] "Kwh"  PC
 SG_ M2P_SysMaxVolt_B6_17 : 48|16@1+ (1,0) [0|65535] "mv"  PC

BO_ 2335305378 M2P_SUMDATA42__18: 8 MBMU
 SG_ M2P_Power_B6_18 : 0|16@1+ (1,-20000) [-20000|45535] "Kw"  PC
 SG_ M2P_SysremEngy_Chg_B6_18 : 16|16@1+ (1,0) [0|65535] "Kwh"  PC
 SG_ M2P_SysremEngy_DisChg_B6_18 : 32|16@1+ (1,0) [0|65535] "Kwh"  PC
 SG_ M2P_SysMaxVolt_B6_18 : 48|16@1+ (1,0) [0|65535] "mv"  PC

BO_ 2335305379 M2P_SUMDATA42__19: 8 MBMU
 SG_ M2P_Power_B6_19 : 0|16@1+ (1,-20000) [-20000|45535] "Kw"  PC
 SG_ M2P_SysremEngy_Chg_B6_19 : 16|16@1+ (1,0) [0|65535] "Kwh"  PC
 SG_ M2P_SysremEngy_DisChg_B6_19 : 32|16@1+ (1,0) [0|65535] "Kwh"  PC
 SG_ M2P_SysMaxVolt_B6_19 : 48|16@1+ (1,0) [0|65535] "mv"  PC

BO_ 2335305380 M2P_SUMDATA42__20: 8 MBMU
 SG_ M2P_Power_B6_20 : 0|16@1+ (1,-20000) [-20000|45535] "Kw"  PC
 SG_ M2P_SysremEngy_Chg_B6_20 : 16|16@1+ (1,0) [0|65535] "Kwh"  PC
 SG_ M2P_SysremEngy_DisChg_B6_20 : 32|16@1+ (1,0) [0|65535] "Kwh"  PC
 SG_ M2P_SysMaxVolt_B6_20 : 48|16@1+ (1,0) [0|65535] "mv"  PC

BO_ 2335305381 M2P_SUMDATA42__21: 8 MBMU
 SG_ M2P_Power_B6_21 : 0|16@1+ (1,-20000) [-20000|45535] "Kw"  PC
 SG_ M2P_SysremEngy_Chg_B6_21 : 16|16@1+ (1,0) [0|65535] "Kwh"  PC
 SG_ M2P_SysremEngy_DisChg_B6_21 : 32|16@1+ (1,0) [0|65535] "Kwh"  PC
 SG_ M2P_SysMaxVolt_B6_21 : 48|16@1+ (1,0) [0|65535] "mv"  PC

CM_ SG_ 2334715557 M2P_SysMinVolt_B4_21 "汇流排4单体最小电压";
CM_ SG_ 2334715557 M2P_SysAvgVolt_B4_21 "汇流排4单体平均电压";
CM_ SG_ 2334715557 M2P_BMS_Status_B4 "汇流排4能量状态";
CM_ SG_ 2334715557 M2P_SOC_B4 "汇流排4系统SOC";
CM_ SG_ 2334715557 M2P_SOH_B4 "汇流排4系统SOH";
CM_ SG_ 2334715557 Reserved_21 "预留";
CM_ SG_ 2334715558 M2P_SysMinVolt_B4_22 "汇流排4单体最小电压";
CM_ SG_ 2334715558 M2P_SysAvgVolt_B4_22 "汇流排4单体平均电压";
CM_ SG_ 2334715558 M2P_BMS_Status_B4 "汇流排4能量状态";
CM_ SG_ 2334715558 M2P_SOC_B4 "汇流排4系统SOC";
CM_ SG_ 2334715558 M2P_SOH_B4 "汇流排4系统SOH";
CM_ SG_ 2334715558 Reserved_22 "预留";
CM_ SG_ 2334715559 M2P_SysMinVolt_B4_23 "汇流排4单体最小电压";
CM_ SG_ 2334715559 M2P_SysAvgVolt_B4_23 "汇流排4单体平均电压";
CM_ SG_ 2334715559 M2P_BMS_Status_B4 "汇流排4能量状态";
CM_ SG_ 2334715559 M2P_SOC_B4 "汇流排4系统SOC";
CM_ SG_ 2334715559 M2P_SOH_B4 "汇流排4系统SOH";
CM_ SG_ 2334715559 Reserved_23 "预留";
CM_ SG_ 2334715560 M2P_SysMinVolt_B4_24 "汇流排4单体最小电压";
CM_ SG_ 2334715560 M2P_SysAvgVolt_B4_24 "汇流排4单体平均电压";
CM_ SG_ 2334715560 M2P_BMS_Status_B4 "汇流排4能量状态";
CM_ SG_ 2334715560 M2P_SOC_B4 "汇流排4系统SOC";
CM_ SG_ 2334715560 M2P_SOH_B4 "汇流排4系统SOH";
CM_ SG_ 2334715560 Reserved_24 "预留";
CM_ SG_ 2334715561 M2P_SysMinVolt_B4_25 "汇流排4单体最小电压";
CM_ SG_ 2334715561 M2P_SysAvgVolt_B4_25 "汇流排4单体平均电压";
CM_ SG_ 2334715561 M2P_BMS_Status_B4 "汇流排4能量状态";
CM_ SG_ 2334715561 M2P_SOC_B4 "汇流排4系统SOC";
CM_ SG_ 2334715561 M2P_SOH_B4 "汇流排4系统SOH";
CM_ SG_ 2334715561 Reserved_25 "预留";
CM_ SG_ 2334715562 M2P_SysMinVolt_B4_26 "汇流排4单体最小电压";
CM_ SG_ 2334715562 M2P_SysAvgVolt_B4_26 "汇流排4单体平均电压";
CM_ SG_ 2334715562 M2P_BMS_Status_B4 "汇流排4能量状态";
CM_ SG_ 2334715562 M2P_SOC_B4 "汇流排4系统SOC";
CM_ SG_ 2334715562 M2P_SOH_B4 "汇流排4系统SOH";
CM_ SG_ 2334715562 Reserved_26 "预留";
CM_ SG_ 2334715563 M2P_SysMinVolt_B4_27 "汇流排4单体最小电压";
CM_ SG_ 2334715563 M2P_SysAvgVolt_B4_27 "汇流排4单体平均电压";
CM_ SG_ 2334715563 M2P_BMS_Status_B4 "汇流排4能量状态";
CM_ SG_ 2334715563 M2P_SOC_B4 "汇流排4系统SOC";
CM_ SG_ 2334715563 M2P_SOH_B4 "汇流排4系统SOH";
CM_ SG_ 2334715563 Reserved_27 "预留";
CM_ SG_ 2334715564 M2P_SysMinVolt_B4_28 "汇流排4单体最小电压";
CM_ SG_ 2334715564 M2P_SysAvgVolt_B4_28 "汇流排4单体平均电压";
CM_ SG_ 2334715564 M2P_BMS_Status_B4 "汇流排4能量状态";
CM_ SG_ 2334715564 M2P_SOC_B4 "汇流排4系统SOC";
CM_ SG_ 2334715564 M2P_SOH_B4 "汇流排4系统SOH";
CM_ SG_ 2334715564 Reserved_28 "预留";
CM_ SG_ 2334715565 M2P_SysMinVolt_B4_29 "汇流排4单体最小电压";
CM_ SG_ 2334715565 M2P_SysAvgVolt_B4_29 "汇流排4单体平均电压";
CM_ SG_ 2334715565 M2P_BMS_Status_B4 "汇流排4能量状态";
CM_ SG_ 2334715565 M2P_SOC_B4 "汇流排4系统SOC";
CM_ SG_ 2334715565 M2P_SOH_B4 "汇流排4系统SOH";
CM_ SG_ 2334715565 Reserved_29 "预留";
CM_ SG_ 2334715566 M2P_SysMinVolt_B4_30 "汇流排4单体最小电压";
CM_ SG_ 2334715566 M2P_SysAvgVolt_B4_30 "汇流排4单体平均电压";
CM_ SG_ 2334715566 M2P_BMS_Status_B4 "汇流排4能量状态";
CM_ SG_ 2334715566 M2P_SOC_B4 "汇流排4系统SOC";
CM_ SG_ 2334715566 M2P_SOH_B4 "汇流排4系统SOH";
CM_ SG_ 2334715566 Reserved_30 "预留";
CM_ SG_ 2334715567 M2P_SysMinVolt_B4_31 "汇流排4单体最小电压";
CM_ SG_ 2334715567 M2P_SysAvgVolt_B4_31 "汇流排4单体平均电压";
CM_ SG_ 2334715567 M2P_BMS_Status_B4 "汇流排4能量状态";
CM_ SG_ 2334715567 M2P_SOC_B4 "汇流排4系统SOC";
CM_ SG_ 2334715567 M2P_SOH_B4 "汇流排4系统SOH";
CM_ SG_ 2334715567 Reserved_31 "预留";
CM_ SG_ 2334781073 M2P_SOE_Charge_B4 "汇流排4系可充电SOE";
CM_ SG_ 2334781073 M2P_SOE_Discharge_B4 "汇流排4系可放电SOE";
CM_ SG_ 2334781073 Reserved_01 "预留";
CM_ SG_ 2334781074 M2P_SOE_Charge_B4 "汇流排4系可充电SOE";
CM_ SG_ 2334781074 M2P_SOE_Discharge_B4 "汇流排4系可放电SOE";
CM_ SG_ 2334781074 Reserved_02 "预留";
CM_ SG_ 2334781075 M2P_SOE_Charge_B4 "汇流排4系可充电SOE";
CM_ SG_ 2334781075 M2P_SOE_Discharge_B4 "汇流排4系可放电SOE";
CM_ SG_ 2334781075 Reserved_03 "预留";
CM_ SG_ 2334781076 M2P_SOE_Charge_B4 "汇流排4系可充电SOE";
CM_ SG_ 2334781076 M2P_SOE_Discharge_B4 "汇流排4系可放电SOE";
CM_ SG_ 2334781076 Reserved_04 "预留";
CM_ SG_ 2334781077 M2P_SOE_Charge_B4 "汇流排4系可充电SOE";
CM_ SG_ 2334781077 M2P_SOE_Discharge_B4 "汇流排4系可放电SOE";
CM_ SG_ 2334781077 Reserved_05 "预留";
CM_ SG_ 2334781078 M2P_SOE_Charge_B4 "汇流排4系可充电SOE";
CM_ SG_ 2334781078 M2P_SOE_Discharge_B4 "汇流排4系可放电SOE";
CM_ SG_ 2334781078 Reserved_06 "预留";
CM_ SG_ 2334781079 M2P_SOE_Charge_B4 "汇流排4系可充电SOE";
CM_ SG_ 2334781079 M2P_SOE_Discharge_B4 "汇流排4系可放电SOE";
CM_ SG_ 2334781079 Reserved_07 "预留";
CM_ SG_ 2334781080 M2P_SOE_Charge_B4 "汇流排4系可充电SOE";
CM_ SG_ 2334781080 M2P_SOE_Discharge_B4 "汇流排4系可放电SOE";
CM_ SG_ 2334781080 Reserved_08 "预留";
CM_ SG_ 2334781081 M2P_SOE_Charge_B4 "汇流排4系可充电SOE";
CM_ SG_ 2334781081 M2P_SOE_Discharge_B4 "汇流排4系可放电SOE";
CM_ SG_ 2334781081 Reserved_09 "预留";
CM_ SG_ 2334781082 M2P_SOE_Charge_B4 "汇流排4系可充电SOE";
CM_ SG_ 2334781082 M2P_SOE_Discharge_B4 "汇流排4系可放电SOE";
CM_ SG_ 2334781082 Reserved_10 "预留";
CM_ SG_ 2334781083 M2P_SOE_Charge_B4 "汇流排4系可充电SOE";
CM_ SG_ 2334781083 M2P_SOE_Discharge_B4 "汇流排4系可放电SOE";
CM_ SG_ 2334781083 Reserved_11 "预留";
CM_ SG_ 2334781084 M2P_SOE_Charge_B4 "汇流排4系可充电SOE";
CM_ SG_ 2334781084 M2P_SOE_Discharge_B4 "汇流排4系可放电SOE";
CM_ SG_ 2334781084 Reserved_12 "预留";
CM_ SG_ 2334781085 M2P_SOE_Charge_B4 "汇流排4系可充电SOE";
CM_ SG_ 2334781085 M2P_SOE_Discharge_B4 "汇流排4系可放电SOE";
CM_ SG_ 2334781085 Reserved_13 "预留";
CM_ SG_ 2334781086 M2P_SOE_Charge_B4 "汇流排4系可充电SOE";
CM_ SG_ 2334781086 M2P_SOE_Discharge_B4 "汇流排4系可放电SOE";
CM_ SG_ 2334781086 Reserved_14 "预留";
CM_ SG_ 2334781087 M2P_SOE_Charge_B4 "汇流排4系可充电SOE";
CM_ SG_ 2334781087 M2P_SOE_Discharge_B4 "汇流排4系可放电SOE";
CM_ SG_ 2334781087 Reserved_15 "预留";
CM_ SG_ 2334781088 M2P_SOE_Charge_B4 "汇流排4系可充电SOE";
CM_ SG_ 2334781088 M2P_SOE_Discharge_B4 "汇流排4系可放电SOE";
CM_ SG_ 2334781088 Reserved_16 "预留";
CM_ SG_ 2334781089 M2P_SOE_Charge_B4 "汇流排4系可充电SOE";
CM_ SG_ 2334781089 M2P_SOE_Discharge_B4 "汇流排4系可放电SOE";
CM_ SG_ 2334781089 Reserved_17 "预留";
CM_ SG_ 2334781090 M2P_SOE_Charge_B4 "汇流排4系可充电SOE";
CM_ SG_ 2334781090 M2P_SOE_Discharge_B4 "汇流排4系可放电SOE";
CM_ SG_ 2334781090 Reserved_18 "预留";
CM_ SG_ 2334781091 M2P_SOE_Charge_B4 "汇流排4系可充电SOE";
CM_ SG_ 2334781091 M2P_SOE_Discharge_B4 "汇流排4系可放电SOE";
CM_ SG_ 2334781091 Reserved_19 "预留";
CM_ SG_ 2334781092 M2P_SOE_Charge_B4 "汇流排4系可充电SOE";
CM_ SG_ 2334781092 M2P_SOE_Discharge_B4 "汇流排4系可放电SOE";
CM_ SG_ 2334781092 Reserved_20 "预留";
CM_ SG_ 2334781093 M2P_SOE_Charge_B4 "汇流排4系可充电SOE";
CM_ SG_ 2334781093 M2P_SOE_Discharge_B4 "汇流排4系可放电SOE";
CM_ SG_ 2334781093 Reserved_21 "预留";
CM_ SG_ 2334781094 M2P_SOE_Charge_B4 "汇流排4系可充电SOE";
CM_ SG_ 2334781094 M2P_SOE_Discharge_B4 "汇流排4系可放电SOE";
CM_ SG_ 2334781094 Reserved_22 "预留";
CM_ SG_ 2334781095 M2P_SOE_Charge_B4 "汇流排4系可充电SOE";
CM_ SG_ 2334781095 M2P_SOE_Discharge_B4 "汇流排4系可放电SOE";
CM_ SG_ 2334781095 Reserved_23 "预留";
CM_ SG_ 2334781096 M2P_SOE_Charge_B4 "汇流排4系可充电SOE";
CM_ SG_ 2334781096 M2P_SOE_Discharge_B4 "汇流排4系可放电SOE";
CM_ SG_ 2334781096 Reserved_24 "预留";
CM_ SG_ 2334781097 M2P_SOE_Charge_B4 "汇流排4系可充电SOE";
CM_ SG_ 2334781097 M2P_SOE_Discharge_B4 "汇流排4系可放电SOE";
CM_ SG_ 2334781097 Reserved_25 "预留";
CM_ SG_ 2334781098 M2P_SOE_Charge_B4 "汇流排4系可充电SOE";
CM_ SG_ 2334781098 M2P_SOE_Discharge_B4 "汇流排4系可放电SOE";
CM_ SG_ 2334781098 Reserved_26 "预留";
CM_ SG_ 2334781099 M2P_SOE_Charge_B4 "汇流排4系可充电SOE";
CM_ SG_ 2334781099 M2P_SOE_Discharge_B4 "汇流排4系可放电SOE";
CM_ SG_ 2334781099 Reserved_27 "预留";
CM_ SG_ 2334781100 M2P_SOE_Charge_B4 "汇流排4系可充电SOE";
CM_ SG_ 2334781100 M2P_SOE_Discharge_B4 "汇流排4系可放电SOE";
CM_ SG_ 2334781100 Reserved_28 "预留";
CM_ SG_ 2334781101 M2P_SOE_Charge_B4 "汇流排4系可充电SOE";
CM_ SG_ 2334781101 M2P_SOE_Discharge_B4 "汇流排4系可放电SOE";
CM_ SG_ 2334781101 Reserved_29 "预留";
CM_ SG_ 2334781102 M2P_SOE_Charge_B4 "汇流排4系可充电SOE";
CM_ SG_ 2334781102 M2P_SOE_Discharge_B4 "汇流排4系可放电SOE";
CM_ SG_ 2334781102 Reserved_30 "预留";
CM_ SG_ 2334781103 M2P_SOE_Charge_B4 "汇流排4系可充电SOE";
CM_ SG_ 2334781103 M2P_SOE_Discharge_B4 "汇流排4系可放电SOE";
CM_ SG_ 2334781103 Reserved_31 "预留";
CM_ SG_ 2334846609 M2P_Measure_Vol_B5_01 "汇流排5所有高压在线电柜外侧电压平均值    ";
CM_ SG_ 2334846609 M2P_Current_B5_01 "汇流排5所有电柜电流累加和";
CM_ SG_ 2334846609 M2P_PermitMaxCharge_I_B5_01 "汇流排5最大允许充电电流";
CM_ SG_ 2334846609 M2P_PermitMaxDisCharge_I_B5_01 "汇流排5最大允许放电电流";
CM_ SG_ 2334846610 M2P_Measure_Vol_B5_02 "汇流排5所有高压在线电柜外侧电压平均值    ";
CM_ SG_ 2334846610 M2P_Current_B5_02 "汇流排5所有电柜电流累加和";
CM_ SG_ 2334846610 M2P_PermitMaxCharge_I_B5_02 "汇流排5最大允许充电电流";
CM_ SG_ 2334846610 M2P_PermitMaxDisCharge_I_B5_02 "汇流排5最大允许放电电流";
CM_ SG_ 2334846611 M2P_Measure_Vol_B5_03 "汇流排5所有高压在线电柜外侧电压平均值    ";
CM_ SG_ 2334846611 M2P_Current_B5_03 "汇流排5所有电柜电流累加和";
CM_ SG_ 2334846611 M2P_PermitMaxCharge_I_B5_03 "汇流排5最大允许充电电流";
CM_ SG_ 2334846611 M2P_PermitMaxDisCharge_I_B5_03 "汇流排5最大允许放电电流";
CM_ SG_ 2334846612 M2P_Measure_Vol_B5_04 "汇流排5所有高压在线电柜外侧电压平均值    ";
CM_ SG_ 2334846612 M2P_Current_B5_04 "汇流排5所有电柜电流累加和";
CM_ SG_ 2334846612 M2P_PermitMaxCharge_I_B5_04 "汇流排5最大允许充电电流";
CM_ SG_ 2334846612 M2P_PermitMaxDisCharge_I_B5_04 "汇流排5最大允许放电电流";
CM_ SG_ 2334846613 M2P_Measure_Vol_B5_05 "汇流排5所有高压在线电柜外侧电压平均值    ";
CM_ SG_ 2334846613 M2P_Current_B5_05 "汇流排5所有电柜电流累加和";
CM_ SG_ 2334846613 M2P_PermitMaxCharge_I_B5_05 "汇流排5最大允许充电电流";
CM_ SG_ 2334846613 M2P_PermitMaxDisCharge_I_B5_05 "汇流排5最大允许放电电流";
CM_ SG_ 2334846614 M2P_Measure_Vol_B5_06 "汇流排5所有高压在线电柜外侧电压平均值    ";
CM_ SG_ 2334846614 M2P_Current_B5_06 "汇流排5所有电柜电流累加和";
CM_ SG_ 2334846614 M2P_PermitMaxCharge_I_B5_06 "汇流排5最大允许充电电流";
CM_ SG_ 2334846614 M2P_PermitMaxDisCharge_I_B5_06 "汇流排5最大允许放电电流";
CM_ SG_ 2334846615 M2P_Measure_Vol_B5_07 "汇流排5所有高压在线电柜外侧电压平均值    ";
CM_ SG_ 2334846615 M2P_Current_B5_07 "汇流排5所有电柜电流累加和";
CM_ SG_ 2334846615 M2P_PermitMaxCharge_I_B5_07 "汇流排5最大允许充电电流";
CM_ SG_ 2334846615 M2P_PermitMaxDisCharge_I_B5_07 "汇流排5最大允许放电电流";
CM_ SG_ 2334846616 M2P_Measure_Vol_B5_08 "汇流排5所有高压在线电柜外侧电压平均值    ";
CM_ SG_ 2334846616 M2P_Current_B5_08 "汇流排5所有电柜电流累加和";
CM_ SG_ 2334846616 M2P_PermitMaxCharge_I_B5_08 "汇流排5最大允许充电电流";
CM_ SG_ 2334846616 M2P_PermitMaxDisCharge_I_B5_08 "汇流排5最大允许放电电流";
CM_ SG_ 2334846617 M2P_Measure_Vol_B5_09 "汇流排5所有高压在线电柜外侧电压平均值    ";
CM_ SG_ 2334846617 M2P_Current_B5_09 "汇流排5所有电柜电流累加和";
CM_ SG_ 2334846617 M2P_PermitMaxCharge_I_B5_09 "汇流排5最大允许充电电流";
CM_ SG_ 2334846617 M2P_PermitMaxDisCharge_I_B5_09 "汇流排5最大允许放电电流";
CM_ SG_ 2334846618 M2P_Measure_Vol_B5_10 "汇流排5所有高压在线电柜外侧电压平均值    ";
CM_ SG_ 2334846618 M2P_Current_B5_10 "汇流排5所有电柜电流累加和";
CM_ SG_ 2334846618 M2P_PermitMaxCharge_I_B5_10 "汇流排5最大允许充电电流";
CM_ SG_ 2334846618 M2P_PermitMaxDisCharge_I_B5_10 "汇流排5最大允许放电电流";
CM_ SG_ 2334846619 M2P_Measure_Vol_B5_11 "汇流排5所有高压在线电柜外侧电压平均值    ";
CM_ SG_ 2334846619 M2P_Current_B5_11 "汇流排5所有电柜电流累加和";
CM_ SG_ 2334846619 M2P_PermitMaxCharge_I_B5_11 "汇流排5最大允许充电电流";
CM_ SG_ 2334846619 M2P_PermitMaxDisCharge_I_B5_11 "汇流排5最大允许放电电流";
CM_ SG_ 2334846620 M2P_Measure_Vol_B5_12 "汇流排5所有高压在线电柜外侧电压平均值    ";
CM_ SG_ 2334846620 M2P_Current_B5_12 "汇流排5所有电柜电流累加和";
CM_ SG_ 2334846620 M2P_PermitMaxCharge_I_B5_12 "汇流排5最大允许充电电流";
CM_ SG_ 2334846620 M2P_PermitMaxDisCharge_I_B5_12 "汇流排5最大允许放电电流";
CM_ SG_ 2334846621 M2P_Measure_Vol_B5_13 "汇流排5所有高压在线电柜外侧电压平均值    ";
CM_ SG_ 2334846621 M2P_Current_B5_13 "汇流排5所有电柜电流累加和";
CM_ SG_ 2334846621 M2P_PermitMaxCharge_I_B5_13 "汇流排5最大允许充电电流";
CM_ SG_ 2334846621 M2P_PermitMaxDisCharge_I_B5_13 "汇流排5最大允许放电电流";
CM_ SG_ 2334846622 M2P_Measure_Vol_B5_14 "汇流排5所有高压在线电柜外侧电压平均值    ";
CM_ SG_ 2334846622 M2P_Current_B5_14 "汇流排5所有电柜电流累加和";
CM_ SG_ 2334846622 M2P_PermitMaxCharge_I_B5_14 "汇流排5最大允许充电电流";
CM_ SG_ 2334846622 M2P_PermitMaxDisCharge_I_B5_14 "汇流排5最大允许放电电流";
CM_ SG_ 2334846623 M2P_Measure_Vol_B5_15 "汇流排5所有高压在线电柜外侧电压平均值    ";
CM_ SG_ 2334846623 M2P_Current_B5_15 "汇流排5所有电柜电流累加和";
CM_ SG_ 2334846623 M2P_PermitMaxCharge_I_B5_15 "汇流排5最大允许充电电流";
CM_ SG_ 2334846623 M2P_PermitMaxDisCharge_I_B5_15 "汇流排5最大允许放电电流";
CM_ SG_ 2334846624 M2P_Measure_Vol_B5_16 "汇流排5所有高压在线电柜外侧电压平均值    ";
CM_ SG_ 2334846624 M2P_Current_B5_16 "汇流排5所有电柜电流累加和";
CM_ SG_ 2334846624 M2P_PermitMaxCharge_I_B5_16 "汇流排5最大允许充电电流";
CM_ SG_ 2334846624 M2P_PermitMaxDisCharge_I_B5_16 "汇流排5最大允许放电电流";
CM_ SG_ 2334846625 M2P_Measure_Vol_B5_17 "汇流排5所有高压在线电柜外侧电压平均值    ";
CM_ SG_ 2334846625 M2P_Current_B5_17 "汇流排5所有电柜电流累加和";
CM_ SG_ 2334846625 M2P_PermitMaxCharge_I_B5_17 "汇流排5最大允许充电电流";
CM_ SG_ 2334846625 M2P_PermitMaxDisCharge_I_B5_17 "汇流排5最大允许放电电流";
CM_ SG_ 2334846626 M2P_Measure_Vol_B5_18 "汇流排5所有高压在线电柜外侧电压平均值    ";
CM_ SG_ 2334846626 M2P_Current_B5_18 "汇流排5所有电柜电流累加和";
CM_ SG_ 2334846626 M2P_PermitMaxCharge_I_B5_18 "汇流排5最大允许充电电流";
CM_ SG_ 2334846626 M2P_PermitMaxDisCharge_I_B5_18 "汇流排5最大允许放电电流";
CM_ SG_ 2334846627 M2P_Measure_Vol_B5_19 "汇流排5所有高压在线电柜外侧电压平均值    ";
CM_ SG_ 2334846627 M2P_Current_B5_19 "汇流排5所有电柜电流累加和";
CM_ SG_ 2334846627 M2P_PermitMaxCharge_I_B5_19 "汇流排5最大允许充电电流";
CM_ SG_ 2334846627 M2P_PermitMaxDisCharge_I_B5_19 "汇流排5最大允许放电电流";
CM_ SG_ 2334846628 M2P_Measure_Vol_B5_20 "汇流排5所有高压在线电柜外侧电压平均值    ";
CM_ SG_ 2334846628 M2P_Current_B5_20 "汇流排5所有电柜电流累加和";
CM_ SG_ 2334846628 M2P_PermitMaxCharge_I_B5_20 "汇流排5最大允许充电电流";
CM_ SG_ 2334846628 M2P_PermitMaxDisCharge_I_B5_20 "汇流排5最大允许放电电流";
CM_ SG_ 2334846629 M2P_Measure_Vol_B5_21 "汇流排5所有高压在线电柜外侧电压平均值    ";
CM_ SG_ 2334846629 M2P_Current_B5_21 "汇流排5所有电柜电流累加和";
CM_ SG_ 2334846629 M2P_PermitMaxCharge_I_B5_21 "汇流排5最大允许充电电流";
CM_ SG_ 2334846629 M2P_PermitMaxDisCharge_I_B5_21 "汇流排5最大允许放电电流";
CM_ SG_ 2334846630 M2P_Measure_Vol_B5_22 "汇流排5所有高压在线电柜外侧电压平均值    ";
CM_ SG_ 2334846630 M2P_Current_B5_22 "汇流排5所有电柜电流累加和";
CM_ SG_ 2334846630 M2P_PermitMaxCharge_I_B5_22 "汇流排5最大允许充电电流";
CM_ SG_ 2334846630 M2P_PermitMaxDisCharge_I_B5_22 "汇流排5最大允许放电电流";
CM_ SG_ 2334846631 M2P_Measure_Vol_B5_23 "汇流排5所有高压在线电柜外侧电压平均值    ";
CM_ SG_ 2334846631 M2P_Current_B5_23 "汇流排5所有电柜电流累加和";
CM_ SG_ 2334846631 M2P_PermitMaxCharge_I_B5_23 "汇流排5最大允许充电电流";
CM_ SG_ 2334846631 M2P_PermitMaxDisCharge_I_B5_23 "汇流排5最大允许放电电流";
CM_ SG_ 2334846632 M2P_Measure_Vol_B5_24 "汇流排5所有高压在线电柜外侧电压平均值    ";
CM_ SG_ 2334846632 M2P_Current_B5_24 "汇流排5所有电柜电流累加和";
CM_ SG_ 2334846632 M2P_PermitMaxCharge_I_B5_24 "汇流排5最大允许充电电流";
CM_ SG_ 2334846632 M2P_PermitMaxDisCharge_I_B5_24 "汇流排5最大允许放电电流";
CM_ SG_ 2334846633 M2P_Measure_Vol_B5_25 "汇流排5所有高压在线电柜外侧电压平均值    ";
CM_ SG_ 2334846633 M2P_Current_B5_25 "汇流排5所有电柜电流累加和";
CM_ SG_ 2334846633 M2P_PermitMaxCharge_I_B5_25 "汇流排5最大允许充电电流";
CM_ SG_ 2334846633 M2P_PermitMaxDisCharge_I_B5_25 "汇流排5最大允许放电电流";
CM_ SG_ 2334846634 M2P_Measure_Vol_B5_26 "汇流排5所有高压在线电柜外侧电压平均值    ";
CM_ SG_ 2334846634 M2P_Current_B5_26 "汇流排5所有电柜电流累加和";
CM_ SG_ 2334846634 M2P_PermitMaxCharge_I_B5_26 "汇流排5最大允许充电电流";
CM_ SG_ 2334846634 M2P_PermitMaxDisCharge_I_B5_26 "汇流排5最大允许放电电流";
CM_ SG_ 2334846635 M2P_Measure_Vol_B5_27 "汇流排5所有高压在线电柜外侧电压平均值    ";
CM_ SG_ 2334846635 M2P_Current_B5_27 "汇流排5所有电柜电流累加和";
CM_ SG_ 2334846635 M2P_PermitMaxCharge_I_B5_27 "汇流排5最大允许充电电流";
CM_ SG_ 2334846635 M2P_PermitMaxDisCharge_I_B5_27 "汇流排5最大允许放电电流";
CM_ SG_ 2334846636 M2P_Measure_Vol_B5_28 "汇流排5所有高压在线电柜外侧电压平均值    ";
CM_ SG_ 2334846636 M2P_Current_B5_28 "汇流排5所有电柜电流累加和";
CM_ SG_ 2334846636 M2P_PermitMaxCharge_I_B5_28 "汇流排5最大允许充电电流";
CM_ SG_ 2334846636 M2P_PermitMaxDisCharge_I_B5_28 "汇流排5最大允许放电电流";
CM_ SG_ 2334846637 M2P_Measure_Vol_B5_29 "汇流排5所有高压在线电柜外侧电压平均值    ";
CM_ SG_ 2334846637 M2P_Current_B5_29 "汇流排5所有电柜电流累加和";
CM_ SG_ 2334846637 M2P_PermitMaxCharge_I_B5_29 "汇流排5最大允许充电电流";
CM_ SG_ 2334846637 M2P_PermitMaxDisCharge_I_B5_29 "汇流排5最大允许放电电流";
CM_ SG_ 2334846638 M2P_Measure_Vol_B5_30 "汇流排5所有高压在线电柜外侧电压平均值    ";
CM_ SG_ 2334846638 M2P_Current_B5_30 "汇流排5所有电柜电流累加和";
CM_ SG_ 2334846638 M2P_PermitMaxCharge_I_B5_30 "汇流排5最大允许充电电流";
CM_ SG_ 2334846638 M2P_PermitMaxDisCharge_I_B5_30 "汇流排5最大允许放电电流";
CM_ SG_ 2334846639 M2P_Measure_Vol_B5_31 "汇流排5所有高压在线电柜外侧电压平均值    ";
CM_ SG_ 2334846639 M2P_Current_B5_31 "汇流排5所有电柜电流累加和";
CM_ SG_ 2334846639 M2P_PermitMaxCharge_I_B5_31 "汇流排5最大允许充电电流";
CM_ SG_ 2334846639 M2P_PermitMaxDisCharge_I_B5_31 "汇流排5最大允许放电电流";
CM_ SG_ 2334912145 M2P_PermitMaxVolt_B5_01 "汇流排5最高允许充电电压 （配置量）";
CM_ SG_ 2334912145 M2P_PermitMinVolt_B5_01 "汇流排5最低允许放电电压 （配置量）";
CM_ SG_ 2334912145 M2P_PermitMaxPow_Chg_B5_01 "汇流排5最大允许充电功率";
CM_ SG_ 2334912145 M2P_PermitMaxPow_DisChg_B5_01 "汇流排5最大允许放电功率";
CM_ SG_ 2334912146 M2P_PermitMaxVolt_B5_02 "汇流排5最高允许充电电压 （配置量）";
CM_ SG_ 2334912146 M2P_PermitMinVolt_B5_02 "汇流排5最低允许放电电压 （配置量）";
CM_ SG_ 2334912146 M2P_PermitMaxPow_Chg_B5_02 "汇流排5最大允许充电功率";
CM_ SG_ 2334912146 M2P_PermitMaxPow_DisChg_B5_02 "汇流排5最大允许放电功率";
CM_ SG_ 2334912147 M2P_PermitMaxVolt_B5_03 "汇流排5最高允许充电电压 （配置量）";
CM_ SG_ 2334912147 M2P_PermitMinVolt_B5_03 "汇流排5最低允许放电电压 （配置量）";
CM_ SG_ 2334912147 M2P_PermitMaxPow_Chg_B5_03 "汇流排5最大允许充电功率";
CM_ SG_ 2334912147 M2P_PermitMaxPow_DisChg_B5_03 "汇流排5最大允许放电功率";
CM_ SG_ 2334912148 M2P_PermitMaxVolt_B5_04 "汇流排5最高允许充电电压 （配置量）";
CM_ SG_ 2334912148 M2P_PermitMinVolt_B5_04 "汇流排5最低允许放电电压 （配置量）";
CM_ SG_ 2334912148 M2P_PermitMaxPow_Chg_B5_04 "汇流排5最大允许充电功率";
CM_ SG_ 2334912148 M2P_PermitMaxPow_DisChg_B5_04 "汇流排5最大允许放电功率";
CM_ SG_ 2334912149 M2P_PermitMaxVolt_B5_05 "汇流排5最高允许充电电压 （配置量）";
CM_ SG_ 2334912149 M2P_PermitMinVolt_B5_05 "汇流排5最低允许放电电压 （配置量）";
CM_ SG_ 2334912149 M2P_PermitMaxPow_Chg_B5_05 "汇流排5最大允许充电功率";
CM_ SG_ 2334912149 M2P_PermitMaxPow_DisChg_B5_05 "汇流排5最大允许放电功率";
CM_ SG_ 2334912150 M2P_PermitMaxVolt_B5_06 "汇流排5最高允许充电电压 （配置量）";
CM_ SG_ 2334912150 M2P_PermitMinVolt_B5_06 "汇流排5最低允许放电电压 （配置量）";
CM_ SG_ 2334912150 M2P_PermitMaxPow_Chg_B5_06 "汇流排5最大允许充电功率";
CM_ SG_ 2334912150 M2P_PermitMaxPow_DisChg_B5_06 "汇流排5最大允许放电功率";
CM_ SG_ 2334912151 M2P_PermitMaxVolt_B5_07 "汇流排5最高允许充电电压 （配置量）";
CM_ SG_ 2334912151 M2P_PermitMinVolt_B5_07 "汇流排5最低允许放电电压 （配置量）";
CM_ SG_ 2334912151 M2P_PermitMaxPow_Chg_B5_07 "汇流排5最大允许充电功率";
CM_ SG_ 2334912151 M2P_PermitMaxPow_DisChg_B5_07 "汇流排5最大允许放电功率";
CM_ SG_ 2334912152 M2P_PermitMaxVolt_B5_08 "汇流排5最高允许充电电压 （配置量）";
CM_ SG_ 2334912152 M2P_PermitMinVolt_B5_08 "汇流排5最低允许放电电压 （配置量）";
CM_ SG_ 2334912152 M2P_PermitMaxPow_Chg_B5_08 "汇流排5最大允许充电功率";
CM_ SG_ 2334912152 M2P_PermitMaxPow_DisChg_B5_08 "汇流排5最大允许放电功率";
CM_ SG_ 2334912153 M2P_PermitMaxVolt_B5_09 "汇流排5最高允许充电电压 （配置量）";
CM_ SG_ 2334912153 M2P_PermitMinVolt_B5_09 "汇流排5最低允许放电电压 （配置量）";
CM_ SG_ 2334912153 M2P_PermitMaxPow_Chg_B5_09 "汇流排5最大允许充电功率";
CM_ SG_ 2334912153 M2P_PermitMaxPow_DisChg_B5_09 "汇流排5最大允许放电功率";
CM_ SG_ 2334912154 M2P_PermitMaxVolt_B5_10 "汇流排5最高允许充电电压 （配置量）";
CM_ SG_ 2334912154 M2P_PermitMinVolt_B5_10 "汇流排5最低允许放电电压 （配置量）";
CM_ SG_ 2334912154 M2P_PermitMaxPow_Chg_B5_10 "汇流排5最大允许充电功率";
CM_ SG_ 2334912154 M2P_PermitMaxPow_DisChg_B5_10 "汇流排5最大允许放电功率";
CM_ SG_ 2334912155 M2P_PermitMaxVolt_B5_11 "汇流排5最高允许充电电压 （配置量）";
CM_ SG_ 2334912155 M2P_PermitMinVolt_B5_11 "汇流排5最低允许放电电压 （配置量）";
CM_ SG_ 2334912155 M2P_PermitMaxPow_Chg_B5_11 "汇流排5最大允许充电功率";
CM_ SG_ 2334912155 M2P_PermitMaxPow_DisChg_B5_11 "汇流排5最大允许放电功率";
CM_ SG_ 2334912156 M2P_PermitMaxVolt_B5_12 "汇流排5最高允许充电电压 （配置量）";
CM_ SG_ 2334912156 M2P_PermitMinVolt_B5_12 "汇流排5最低允许放电电压 （配置量）";
CM_ SG_ 2334912156 M2P_PermitMaxPow_Chg_B5_12 "汇流排5最大允许充电功率";
CM_ SG_ 2334912156 M2P_PermitMaxPow_DisChg_B5_12 "汇流排5最大允许放电功率";
CM_ SG_ 2334912157 M2P_PermitMaxVolt_B5_13 "汇流排5最高允许充电电压 （配置量）";
CM_ SG_ 2334912157 M2P_PermitMinVolt_B5_13 "汇流排5最低允许放电电压 （配置量）";
CM_ SG_ 2334912157 M2P_PermitMaxPow_Chg_B5_13 "汇流排5最大允许充电功率";
CM_ SG_ 2334912157 M2P_PermitMaxPow_DisChg_B5_13 "汇流排5最大允许放电功率";
CM_ SG_ 2334912158 M2P_PermitMaxVolt_B5_14 "汇流排5最高允许充电电压 （配置量）";
CM_ SG_ 2334912158 M2P_PermitMinVolt_B5_14 "汇流排5最低允许放电电压 （配置量）";
CM_ SG_ 2334912158 M2P_PermitMaxPow_Chg_B5_14 "汇流排5最大允许充电功率";
CM_ SG_ 2334912158 M2P_PermitMaxPow_DisChg_B5_14 "汇流排5最大允许放电功率";
CM_ SG_ 2334912159 M2P_PermitMaxVolt_B5_15 "汇流排5最高允许充电电压 （配置量）";
CM_ SG_ 2334912159 M2P_PermitMinVolt_B5_15 "汇流排5最低允许放电电压 （配置量）";
CM_ SG_ 2334912159 M2P_PermitMaxPow_Chg_B5_15 "汇流排5最大允许充电功率";
CM_ SG_ 2334912159 M2P_PermitMaxPow_DisChg_B5_15 "汇流排5最大允许放电功率";
CM_ SG_ 2334912160 M2P_PermitMaxVolt_B5_16 "汇流排5最高允许充电电压 （配置量）";
CM_ SG_ 2334912160 M2P_PermitMinVolt_B5_16 "汇流排5最低允许放电电压 （配置量）";
CM_ SG_ 2334912160 M2P_PermitMaxPow_Chg_B5_16 "汇流排5最大允许充电功率";
CM_ SG_ 2334912160 M2P_PermitMaxPow_DisChg_B5_16 "汇流排5最大允许放电功率";
CM_ SG_ 2334912161 M2P_PermitMaxVolt_B5_17 "汇流排5最高允许充电电压 （配置量）";
CM_ SG_ 2334912161 M2P_PermitMinVolt_B5_17 "汇流排5最低允许放电电压 （配置量）";
CM_ SG_ 2334912161 M2P_PermitMaxPow_Chg_B5_17 "汇流排5最大允许充电功率";
CM_ SG_ 2334912161 M2P_PermitMaxPow_DisChg_B5_17 "汇流排5最大允许放电功率";
CM_ SG_ 2334912162 M2P_PermitMaxVolt_B5_18 "汇流排5最高允许充电电压 （配置量）";
CM_ SG_ 2334912162 M2P_PermitMinVolt_B5_18 "汇流排5最低允许放电电压 （配置量）";
CM_ SG_ 2334912162 M2P_PermitMaxPow_Chg_B5_18 "汇流排5最大允许充电功率";
CM_ SG_ 2334912162 M2P_PermitMaxPow_DisChg_B5_18 "汇流排5最大允许放电功率";
CM_ SG_ 2334912163 M2P_PermitMaxVolt_B5_19 "汇流排5最高允许充电电压 （配置量）";
CM_ SG_ 2334912163 M2P_PermitMinVolt_B5_19 "汇流排5最低允许放电电压 （配置量）";
CM_ SG_ 2334912163 M2P_PermitMaxPow_Chg_B5_19 "汇流排5最大允许充电功率";
CM_ SG_ 2334912163 M2P_PermitMaxPow_DisChg_B5_19 "汇流排5最大允许放电功率";
CM_ SG_ 2334912164 M2P_PermitMaxVolt_B5_20 "汇流排5最高允许充电电压 （配置量）";
CM_ SG_ 2334912164 M2P_PermitMinVolt_B5_20 "汇流排5最低允许放电电压 （配置量）";
CM_ SG_ 2334912164 M2P_PermitMaxPow_Chg_B5_20 "汇流排5最大允许充电功率";
CM_ SG_ 2334912164 M2P_PermitMaxPow_DisChg_B5_20 "汇流排5最大允许放电功率";
CM_ SG_ 2334912165 M2P_PermitMaxVolt_B5_21 "汇流排5最高允许充电电压 （配置量）";
CM_ SG_ 2334912165 M2P_PermitMinVolt_B5_21 "汇流排5最低允许放电电压 （配置量）";
CM_ SG_ 2334912165 M2P_PermitMaxPow_Chg_B5_21 "汇流排5最大允许充电功率";
CM_ SG_ 2334912165 M2P_PermitMaxPow_DisChg_B5_21 "汇流排5最大允许放电功率";
CM_ SG_ 2334912166 M2P_PermitMaxVolt_B5_22 "汇流排5最高允许充电电压 （配置量）";
CM_ SG_ 2334912166 M2P_PermitMinVolt_B5_22 "汇流排5最低允许放电电压 （配置量）";
CM_ SG_ 2334912166 M2P_PermitMaxPow_Chg_B5_22 "汇流排5最大允许充电功率";
CM_ SG_ 2334912166 M2P_PermitMaxPow_DisChg_B5_22 "汇流排5最大允许放电功率";
CM_ SG_ 2334912167 M2P_PermitMaxVolt_B5_23 "汇流排5最高允许充电电压 （配置量）";
CM_ SG_ 2334912167 M2P_PermitMinVolt_B5_23 "汇流排5最低允许放电电压 （配置量）";
CM_ SG_ 2334912167 M2P_PermitMaxPow_Chg_B5_23 "汇流排5最大允许充电功率";
CM_ SG_ 2334912167 M2P_PermitMaxPow_DisChg_B5_23 "汇流排5最大允许放电功率";
CM_ SG_ 2334912168 M2P_PermitMaxVolt_B5_24 "汇流排5最高允许充电电压 （配置量）";
CM_ SG_ 2334912168 M2P_PermitMinVolt_B5_24 "汇流排5最低允许放电电压 （配置量）";
CM_ SG_ 2334912168 M2P_PermitMaxPow_Chg_B5_24 "汇流排5最大允许充电功率";
CM_ SG_ 2334912168 M2P_PermitMaxPow_DisChg_B5_24 "汇流排5最大允许放电功率";
CM_ SG_ 2334912169 M2P_PermitMaxVolt_B5_25 "汇流排5最高允许充电电压 （配置量）";
CM_ SG_ 2334912169 M2P_PermitMinVolt_B5_25 "汇流排5最低允许放电电压 （配置量）";
CM_ SG_ 2334912169 M2P_PermitMaxPow_Chg_B5_25 "汇流排5最大允许充电功率";
CM_ SG_ 2334912169 M2P_PermitMaxPow_DisChg_B5_25 "汇流排5最大允许放电功率";
CM_ SG_ 2334912170 M2P_PermitMaxVolt_B5_26 "汇流排5最高允许充电电压 （配置量）";
CM_ SG_ 2334912170 M2P_PermitMinVolt_B5_26 "汇流排5最低允许放电电压 （配置量）";
CM_ SG_ 2334912170 M2P_PermitMaxPow_Chg_B5_26 "汇流排5最大允许充电功率";
CM_ SG_ 2334912170 M2P_PermitMaxPow_DisChg_B5_26 "汇流排5最大允许放电功率";
CM_ SG_ 2334912171 M2P_PermitMaxVolt_B5_27 "汇流排5最高允许充电电压 （配置量）";
CM_ SG_ 2334912171 M2P_PermitMinVolt_B5_27 "汇流排5最低允许放电电压 （配置量）";
CM_ SG_ 2334912171 M2P_PermitMaxPow_Chg_B5_27 "汇流排5最大允许充电功率";
CM_ SG_ 2334912171 M2P_PermitMaxPow_DisChg_B5_27 "汇流排5最大允许放电功率";
CM_ SG_ 2334912172 M2P_PermitMaxVolt_B5_28 "汇流排5最高允许充电电压 （配置量）";
CM_ SG_ 2334912172 M2P_PermitMinVolt_B5_28 "汇流排5最低允许放电电压 （配置量）";
CM_ SG_ 2334912172 M2P_PermitMaxPow_Chg_B5_28 "汇流排5最大允许充电功率";
CM_ SG_ 2334912172 M2P_PermitMaxPow_DisChg_B5_28 "汇流排5最大允许放电功率";
CM_ SG_ 2334912173 M2P_PermitMaxVolt_B5_29 "汇流排5最高允许充电电压 （配置量）";
CM_ SG_ 2334912173 M2P_PermitMinVolt_B5_29 "汇流排5最低允许放电电压 （配置量）";
CM_ SG_ 2334912173 M2P_PermitMaxPow_Chg_B5_29 "汇流排5最大允许充电功率";
CM_ SG_ 2334912173 M2P_PermitMaxPow_DisChg_B5_29 "汇流排5最大允许放电功率";
CM_ SG_ 2334912174 M2P_PermitMaxVolt_B5_30 "汇流排5最高允许充电电压 （配置量）";
CM_ SG_ 2334912174 M2P_PermitMinVolt_B5_30 "汇流排5最低允许放电电压 （配置量）";
CM_ SG_ 2334912174 M2P_PermitMaxPow_Chg_B5_30 "汇流排5最大允许充电功率";
CM_ SG_ 2334912174 M2P_PermitMaxPow_DisChg_B5_30 "汇流排5最大允许放电功率";
CM_ SG_ 2334912175 M2P_PermitMaxVolt_B5_31 "汇流排5最高允许充电电压 （配置量）";
CM_ SG_ 2334912175 M2P_PermitMinVolt_B5_31 "汇流排5最低允许放电电压 （配置量）";
CM_ SG_ 2334912175 M2P_PermitMaxPow_Chg_B5_31 "汇流排5最大允许充电功率";
CM_ SG_ 2334912175 M2P_PermitMaxPow_DisChg_B5_31 "汇流排5最大允许放电功率";
CM_ SG_ 2334977681 M2P_Power_B5_01 "汇流排5实时功率";
CM_ SG_ 2334977681 M2P_SysremEngy_Chg_B5_01 "汇流排5充电剩余能量";
CM_ SG_ 2334977681 M2P_SysremEngy_DisChg_B5_01 "汇流排5放电剩余能量";
CM_ SG_ 2334977681 M2P_SysMaxVolt_B5_01 "汇流排5单体最大电压  ";
CM_ SG_ 2334977682 M2P_Power_B5_02 "汇流排5实时功率";
CM_ SG_ 2334977682 M2P_SysremEngy_Chg_B5_02 "汇流排5充电剩余能量";
CM_ SG_ 2334977682 M2P_SysremEngy_DisChg_B5_02 "汇流排5放电剩余能量";
CM_ SG_ 2334977682 M2P_SysMaxVolt_B5_02 "汇流排5单体最大电压  ";
CM_ SG_ 2334977683 M2P_Power_B5_03 "汇流排5实时功率";
CM_ SG_ 2334977683 M2P_SysremEngy_Chg_B5_03 "汇流排5充电剩余能量";
CM_ SG_ 2334977683 M2P_SysremEngy_DisChg_B5_03 "汇流排5放电剩余能量";
CM_ SG_ 2334977683 M2P_SysMaxVolt_B5_03 "汇流排5单体最大电压  ";
CM_ SG_ 2334977684 M2P_Power_B5_04 "汇流排5实时功率";
CM_ SG_ 2334977684 M2P_SysremEngy_Chg_B5_04 "汇流排5充电剩余能量";
CM_ SG_ 2334977684 M2P_SysremEngy_DisChg_B5_04 "汇流排5放电剩余能量";
CM_ SG_ 2334977684 M2P_SysMaxVolt_B5_04 "汇流排5单体最大电压  ";
CM_ SG_ 2334977685 M2P_Power_B5_05 "汇流排5实时功率";
CM_ SG_ 2334977685 M2P_SysremEngy_Chg_B5_05 "汇流排5充电剩余能量";
CM_ SG_ 2334977685 M2P_SysremEngy_DisChg_B5_05 "汇流排5放电剩余能量";
CM_ SG_ 2334977685 M2P_SysMaxVolt_B5_05 "汇流排5单体最大电压  ";
CM_ SG_ 2334977686 M2P_Power_B5_06 "汇流排5实时功率";
CM_ SG_ 2334977686 M2P_SysremEngy_Chg_B5_06 "汇流排5充电剩余能量";
CM_ SG_ 2334977686 M2P_SysremEngy_DisChg_B5_06 "汇流排5放电剩余能量";
CM_ SG_ 2334977686 M2P_SysMaxVolt_B5_06 "汇流排5单体最大电压  ";
CM_ SG_ 2334977687 M2P_Power_B5_07 "汇流排5实时功率";
CM_ SG_ 2334977687 M2P_SysremEngy_Chg_B5_07 "汇流排5充电剩余能量";
CM_ SG_ 2334977687 M2P_SysremEngy_DisChg_B5_07 "汇流排5放电剩余能量";
CM_ SG_ 2334977687 M2P_SysMaxVolt_B5_07 "汇流排5单体最大电压  ";
CM_ SG_ 2334977688 M2P_Power_B5_08 "汇流排5实时功率";
CM_ SG_ 2334977688 M2P_SysremEngy_Chg_B5_08 "汇流排5充电剩余能量";
CM_ SG_ 2334977688 M2P_SysremEngy_DisChg_B5_08 "汇流排5放电剩余能量";
CM_ SG_ 2334977688 M2P_SysMaxVolt_B5_08 "汇流排5单体最大电压  ";
CM_ SG_ 2334977689 M2P_Power_B5_09 "汇流排5实时功率";
CM_ SG_ 2334977689 M2P_SysremEngy_Chg_B5_09 "汇流排5充电剩余能量";
CM_ SG_ 2334977689 M2P_SysremEngy_DisChg_B5_09 "汇流排5放电剩余能量";
CM_ SG_ 2334977689 M2P_SysMaxVolt_B5_09 "汇流排5单体最大电压  ";
CM_ SG_ 2334977690 M2P_Power_B5_10 "汇流排5实时功率";
CM_ SG_ 2334977690 M2P_SysremEngy_Chg_B5_10 "汇流排5充电剩余能量";
CM_ SG_ 2334977690 M2P_SysremEngy_DisChg_B5_10 "汇流排5放电剩余能量";
CM_ SG_ 2334977690 M2P_SysMaxVolt_B5_10 "汇流排5单体最大电压  ";
CM_ SG_ 2334977691 M2P_Power_B5_11 "汇流排5实时功率";
CM_ SG_ 2334977691 M2P_SysremEngy_Chg_B5_11 "汇流排5充电剩余能量";
CM_ SG_ 2334977691 M2P_SysremEngy_DisChg_B5_11 "汇流排5放电剩余能量";
CM_ SG_ 2334977691 M2P_SysMaxVolt_B5_11 "汇流排5单体最大电压  ";
CM_ SG_ 2334977692 M2P_Power_B5_12 "汇流排5实时功率";
CM_ SG_ 2334977692 M2P_SysremEngy_Chg_B5_12 "汇流排5充电剩余能量";
CM_ SG_ 2334977692 M2P_SysremEngy_DisChg_B5_12 "汇流排5放电剩余能量";
CM_ SG_ 2334977692 M2P_SysMaxVolt_B5_12 "汇流排5单体最大电压  ";
CM_ SG_ 2334977693 M2P_Power_B5_13 "汇流排5实时功率";
CM_ SG_ 2334977693 M2P_SysremEngy_Chg_B5_13 "汇流排5充电剩余能量";
CM_ SG_ 2334977693 M2P_SysremEngy_DisChg_B5_13 "汇流排5放电剩余能量";
CM_ SG_ 2334977693 M2P_SysMaxVolt_B5_13 "汇流排5单体最大电压  ";
CM_ SG_ 2334977694 M2P_Power_B5_14 "汇流排5实时功率";
CM_ SG_ 2334977694 M2P_SysremEngy_Chg_B5_14 "汇流排5充电剩余能量";
CM_ SG_ 2334977694 M2P_SysremEngy_DisChg_B5_14 "汇流排5放电剩余能量";
CM_ SG_ 2334977694 M2P_SysMaxVolt_B5_14 "汇流排5单体最大电压  ";
CM_ SG_ 2334977695 M2P_Power_B5_15 "汇流排5实时功率";
CM_ SG_ 2334977695 M2P_SysremEngy_Chg_B5_15 "汇流排5充电剩余能量";
CM_ SG_ 2334977695 M2P_SysremEngy_DisChg_B5_15 "汇流排5放电剩余能量";
CM_ SG_ 2334977695 M2P_SysMaxVolt_B5_15 "汇流排5单体最大电压  ";
CM_ SG_ 2334977696 M2P_Power_B5_16 "汇流排5实时功率";
CM_ SG_ 2334977696 M2P_SysremEngy_Chg_B5_16 "汇流排5充电剩余能量";
CM_ SG_ 2334977696 M2P_SysremEngy_DisChg_B5_16 "汇流排5放电剩余能量";
CM_ SG_ 2334977696 M2P_SysMaxVolt_B5_16 "汇流排5单体最大电压  ";
CM_ SG_ 2334977697 M2P_Power_B5_17 "汇流排5实时功率";
CM_ SG_ 2334977697 M2P_SysremEngy_Chg_B5_17 "汇流排5充电剩余能量";
CM_ SG_ 2334977697 M2P_SysremEngy_DisChg_B5_17 "汇流排5放电剩余能量";
CM_ SG_ 2334977697 M2P_SysMaxVolt_B5_17 "汇流排5单体最大电压  ";
CM_ SG_ 2334977698 M2P_Power_B5_18 "汇流排5实时功率";
CM_ SG_ 2334977698 M2P_SysremEngy_Chg_B5_18 "汇流排5充电剩余能量";
CM_ SG_ 2334977698 M2P_SysremEngy_DisChg_B5_18 "汇流排5放电剩余能量";
CM_ SG_ 2334977698 M2P_SysMaxVolt_B5_18 "汇流排5单体最大电压  ";
CM_ SG_ 2334977699 M2P_Power_B5_19 "汇流排5实时功率";
CM_ SG_ 2334977699 M2P_SysremEngy_Chg_B5_19 "汇流排5充电剩余能量";
CM_ SG_ 2334977699 M2P_SysremEngy_DisChg_B5_19 "汇流排5放电剩余能量";
CM_ SG_ 2334977699 M2P_SysMaxVolt_B5_19 "汇流排5单体最大电压  ";
CM_ SG_ 2334977700 M2P_Power_B5_20 "汇流排5实时功率";
CM_ SG_ 2334977700 M2P_SysremEngy_Chg_B5_20 "汇流排5充电剩余能量";
CM_ SG_ 2334977700 M2P_SysremEngy_DisChg_B5_20 "汇流排5放电剩余能量";
CM_ SG_ 2334977700 M2P_SysMaxVolt_B5_20 "汇流排5单体最大电压  ";
CM_ SG_ 2334977701 M2P_Power_B5_21 "汇流排5实时功率";
CM_ SG_ 2334977701 M2P_SysremEngy_Chg_B5_21 "汇流排5充电剩余能量";
CM_ SG_ 2334977701 M2P_SysremEngy_DisChg_B5_21 "汇流排5放电剩余能量";
CM_ SG_ 2334977701 M2P_SysMaxVolt_B5_21 "汇流排5单体最大电压  ";
CM_ SG_ 2334977702 M2P_Power_B5_22 "汇流排5实时功率";
CM_ SG_ 2334977702 M2P_SysremEngy_Chg_B5_22 "汇流排5充电剩余能量";
CM_ SG_ 2334977702 M2P_SysremEngy_DisChg_B5_22 "汇流排5放电剩余能量";
CM_ SG_ 2334977702 M2P_SysMaxVolt_B5_22 "汇流排5单体最大电压  ";
CM_ SG_ 2334977703 M2P_Power_B5_23 "汇流排5实时功率";
CM_ SG_ 2334977703 M2P_SysremEngy_Chg_B5_23 "汇流排5充电剩余能量";
CM_ SG_ 2334977703 M2P_SysremEngy_DisChg_B5_23 "汇流排5放电剩余能量";
CM_ SG_ 2334977703 M2P_SysMaxVolt_B5_23 "汇流排5单体最大电压  ";
CM_ SG_ 2334977704 M2P_Power_B5_24 "汇流排5实时功率";
CM_ SG_ 2334977704 M2P_SysremEngy_Chg_B5_24 "汇流排5充电剩余能量";
CM_ SG_ 2334977704 M2P_SysremEngy_DisChg_B5_24 "汇流排5放电剩余能量";
CM_ SG_ 2334977704 M2P_SysMaxVolt_B5_24 "汇流排5单体最大电压  ";
CM_ SG_ 2334977705 M2P_Power_B5_25 "汇流排5实时功率";
CM_ SG_ 2334977705 M2P_SysremEngy_Chg_B5_25 "汇流排5充电剩余能量";
CM_ SG_ 2334977705 M2P_SysremEngy_DisChg_B5_25 "汇流排5放电剩余能量";
CM_ SG_ 2334977705 M2P_SysMaxVolt_B5_25 "汇流排5单体最大电压  ";
CM_ SG_ 2334977706 M2P_Power_B5_26 "汇流排5实时功率";
CM_ SG_ 2334977706 M2P_SysremEngy_Chg_B5_26 "汇流排5充电剩余能量";
CM_ SG_ 2334977706 M2P_SysremEngy_DisChg_B5_26 "汇流排5放电剩余能量";
CM_ SG_ 2334977706 M2P_SysMaxVolt_B5_26 "汇流排5单体最大电压  ";
CM_ SG_ 2334977707 M2P_Power_B5_27 "汇流排5实时功率";
CM_ SG_ 2334977707 M2P_SysremEngy_Chg_B5_27 "汇流排5充电剩余能量";
CM_ SG_ 2334977707 M2P_SysremEngy_DisChg_B5_27 "汇流排5放电剩余能量";
CM_ SG_ 2334977707 M2P_SysMaxVolt_B5_27 "汇流排5单体最大电压  ";
CM_ SG_ 2334977708 M2P_Power_B5_28 "汇流排5实时功率";
CM_ SG_ 2334977708 M2P_SysremEngy_Chg_B5_28 "汇流排5充电剩余能量";
CM_ SG_ 2334977708 M2P_SysremEngy_DisChg_B5_28 "汇流排5放电剩余能量";
CM_ SG_ 2334977708 M2P_SysMaxVolt_B5_28 "汇流排5单体最大电压  ";
CM_ SG_ 2334977709 M2P_Power_B5_29 "汇流排5实时功率";
CM_ SG_ 2334977709 M2P_SysremEngy_Chg_B5_29 "汇流排5充电剩余能量";
CM_ SG_ 2334977709 M2P_SysremEngy_DisChg_B5_29 "汇流排5放电剩余能量";
CM_ SG_ 2334977709 M2P_SysMaxVolt_B5_29 "汇流排5单体最大电压  ";
CM_ SG_ 2334977710 M2P_Power_B5_30 "汇流排5实时功率";
CM_ SG_ 2334977710 M2P_SysremEngy_Chg_B5_30 "汇流排5充电剩余能量";
CM_ SG_ 2334977710 M2P_SysremEngy_DisChg_B5_30 "汇流排5放电剩余能量";
CM_ SG_ 2334977710 M2P_SysMaxVolt_B5_30 "汇流排5单体最大电压  ";
CM_ SG_ 2334977711 M2P_Power_B5_31 "汇流排5实时功率";
CM_ SG_ 2334977711 M2P_SysremEngy_Chg_B5_31 "汇流排5充电剩余能量";
CM_ SG_ 2334977711 M2P_SysremEngy_DisChg_B5_31 "汇流排5放电剩余能量";
CM_ SG_ 2334977711 M2P_SysMaxVolt_B5_31 "汇流排5单体最大电压  ";
CM_ SG_ 2335043217 M2P_SysMinVolt_B5_01 "汇流排5单体最小电压";
CM_ SG_ 2335043217 M2P_SysAvgVolt_B5_01 "汇流排5单体平均电压";
CM_ SG_ 2335043217 M2P_BMS_Status_B5 "汇流排5能量状态";
CM_ SG_ 2335043217 M2P_SOC_B5 "汇流排5系统SOC";
CM_ SG_ 2335043217 M2P_SOH_B5 "汇流排5系统SOH";
CM_ SG_ 2335043217 Reserved_01 "预留";
CM_ SG_ 2335043218 M2P_SysMinVolt_B5_02 "汇流排5单体最小电压";
CM_ SG_ 2335043218 M2P_SysAvgVolt_B5_02 "汇流排5单体平均电压";
CM_ SG_ 2335043218 M2P_BMS_Status_B5 "汇流排5能量状态";
CM_ SG_ 2335043218 M2P_SOC_B5 "汇流排5系统SOC";
CM_ SG_ 2335043218 M2P_SOH_B5 "汇流排5系统SOH";
CM_ SG_ 2335043218 Reserved_02 "预留";
CM_ SG_ 2335043219 M2P_SysMinVolt_B5_03 "汇流排5单体最小电压";
CM_ SG_ 2335043219 M2P_SysAvgVolt_B5_03 "汇流排5单体平均电压";
CM_ SG_ 2335043219 M2P_BMS_Status_B5 "汇流排5能量状态";
CM_ SG_ 2335043219 M2P_SOC_B5 "汇流排5系统SOC";
CM_ SG_ 2335043219 M2P_SOH_B5 "汇流排5系统SOH";
CM_ SG_ 2335043219 Reserved_03 "预留";
CM_ SG_ 2335043220 M2P_SysMinVolt_B5_04 "汇流排5单体最小电压";
CM_ SG_ 2335043220 M2P_SysAvgVolt_B5_04 "汇流排5单体平均电压";
CM_ SG_ 2335043220 M2P_BMS_Status_B5 "汇流排5能量状态";
CM_ SG_ 2335043220 M2P_SOC_B5 "汇流排5系统SOC";
CM_ SG_ 2335043220 M2P_SOH_B5 "汇流排5系统SOH";
CM_ SG_ 2335043220 Reserved_04 "预留";
CM_ SG_ 2335043221 M2P_SysMinVolt_B5_05 "汇流排5单体最小电压";
CM_ SG_ 2335043221 M2P_SysAvgVolt_B5_05 "汇流排5单体平均电压";
CM_ SG_ 2335043221 M2P_BMS_Status_B5 "汇流排5能量状态";
CM_ SG_ 2335043221 M2P_SOC_B5 "汇流排5系统SOC";
CM_ SG_ 2335043221 M2P_SOH_B5 "汇流排5系统SOH";
CM_ SG_ 2335043221 Reserved_05 "预留";
CM_ SG_ 2335043222 M2P_SysMinVolt_B5_06 "汇流排5单体最小电压";
CM_ SG_ 2335043222 M2P_SysAvgVolt_B5_06 "汇流排5单体平均电压";
CM_ SG_ 2335043222 M2P_BMS_Status_B5 "汇流排5能量状态";
CM_ SG_ 2335043222 M2P_SOC_B5 "汇流排5系统SOC";
CM_ SG_ 2335043222 M2P_SOH_B5 "汇流排5系统SOH";
CM_ SG_ 2335043222 Reserved_06 "预留";
CM_ SG_ 2335043223 M2P_SysMinVolt_B5_07 "汇流排5单体最小电压";
CM_ SG_ 2335043223 M2P_SysAvgVolt_B5_07 "汇流排5单体平均电压";
CM_ SG_ 2335043223 M2P_BMS_Status_B5 "汇流排5能量状态";
CM_ SG_ 2335043223 M2P_SOC_B5 "汇流排5系统SOC";
CM_ SG_ 2335043223 M2P_SOH_B5 "汇流排5系统SOH";
CM_ SG_ 2335043223 Reserved_07 "预留";
CM_ SG_ 2335043224 M2P_SysMinVolt_B5_08 "汇流排5单体最小电压";
CM_ SG_ 2335043224 M2P_SysAvgVolt_B5_08 "汇流排5单体平均电压";
CM_ SG_ 2335043224 M2P_BMS_Status_B5 "汇流排5能量状态";
CM_ SG_ 2335043224 M2P_SOC_B5 "汇流排5系统SOC";
CM_ SG_ 2335043224 M2P_SOH_B5 "汇流排5系统SOH";
CM_ SG_ 2335043224 Reserved_08 "预留";
CM_ SG_ 2335043225 M2P_SysMinVolt_B5_09 "汇流排5单体最小电压";
CM_ SG_ 2335043225 M2P_SysAvgVolt_B5_09 "汇流排5单体平均电压";
CM_ SG_ 2335043225 M2P_BMS_Status_B5 "汇流排5能量状态";
CM_ SG_ 2335043225 M2P_SOC_B5 "汇流排5系统SOC";
CM_ SG_ 2335043225 M2P_SOH_B5 "汇流排5系统SOH";
CM_ SG_ 2335043225 Reserved_09 "预留";
CM_ SG_ 2335043226 M2P_SysMinVolt_B5_10 "汇流排5单体最小电压";
CM_ SG_ 2335043226 M2P_SysAvgVolt_B5_10 "汇流排5单体平均电压";
CM_ SG_ 2335043226 M2P_BMS_Status_B5 "汇流排5能量状态";
CM_ SG_ 2335043226 M2P_SOC_B5 "汇流排5系统SOC";
CM_ SG_ 2335043226 M2P_SOH_B5 "汇流排5系统SOH";
CM_ SG_ 2335043226 Reserved_10 "预留";
CM_ SG_ 2335043227 M2P_SysMinVolt_B5_11 "汇流排5单体最小电压";
CM_ SG_ 2335043227 M2P_SysAvgVolt_B5_11 "汇流排5单体平均电压";
CM_ SG_ 2335043227 M2P_BMS_Status_B5 "汇流排5能量状态";
CM_ SG_ 2335043227 M2P_SOC_B5 "汇流排5系统SOC";
CM_ SG_ 2335043227 M2P_SOH_B5 "汇流排5系统SOH";
CM_ SG_ 2335043227 Reserved_11 "预留";
CM_ SG_ 2335043228 M2P_SysMinVolt_B5_12 "汇流排5单体最小电压";
CM_ SG_ 2335043228 M2P_SysAvgVolt_B5_12 "汇流排5单体平均电压";
CM_ SG_ 2335043228 M2P_BMS_Status_B5 "汇流排5能量状态";
CM_ SG_ 2335043228 M2P_SOC_B5 "汇流排5系统SOC";
CM_ SG_ 2335043228 M2P_SOH_B5 "汇流排5系统SOH";
CM_ SG_ 2335043228 Reserved_12 "预留";
CM_ SG_ 2335043229 M2P_SysMinVolt_B5_13 "汇流排5单体最小电压";
CM_ SG_ 2335043229 M2P_SysAvgVolt_B5_13 "汇流排5单体平均电压";
CM_ SG_ 2335043229 M2P_BMS_Status_B5 "汇流排5能量状态";
CM_ SG_ 2335043229 M2P_SOC_B5 "汇流排5系统SOC";
CM_ SG_ 2335043229 M2P_SOH_B5 "汇流排5系统SOH";
CM_ SG_ 2335043229 Reserved_13 "预留";
CM_ SG_ 2335043230 M2P_SysMinVolt_B5_14 "汇流排5单体最小电压";
CM_ SG_ 2335043230 M2P_SysAvgVolt_B5_14 "汇流排5单体平均电压";
CM_ SG_ 2335043230 M2P_BMS_Status_B5 "汇流排5能量状态";
CM_ SG_ 2335043230 M2P_SOC_B5 "汇流排5系统SOC";
CM_ SG_ 2335043230 M2P_SOH_B5 "汇流排5系统SOH";
CM_ SG_ 2335043230 Reserved_14 "预留";
CM_ SG_ 2335043231 M2P_SysMinVolt_B5_15 "汇流排5单体最小电压";
CM_ SG_ 2335043231 M2P_SysAvgVolt_B5_15 "汇流排5单体平均电压";
CM_ SG_ 2335043231 M2P_BMS_Status_B5 "汇流排5能量状态";
CM_ SG_ 2335043231 M2P_SOC_B5 "汇流排5系统SOC";
CM_ SG_ 2335043231 M2P_SOH_B5 "汇流排5系统SOH";
CM_ SG_ 2335043231 Reserved_15 "预留";
CM_ SG_ 2335043232 M2P_SysMinVolt_B5_16 "汇流排5单体最小电压";
CM_ SG_ 2335043232 M2P_SysAvgVolt_B5_16 "汇流排5单体平均电压";
CM_ SG_ 2335043232 M2P_BMS_Status_B5 "汇流排5能量状态";
CM_ SG_ 2335043232 M2P_SOC_B5 "汇流排5系统SOC";
CM_ SG_ 2335043232 M2P_SOH_B5 "汇流排5系统SOH";
CM_ SG_ 2335043232 Reserved_16 "预留";
CM_ SG_ 2335043233 M2P_SysMinVolt_B5_17 "汇流排5单体最小电压";
CM_ SG_ 2335043233 M2P_SysAvgVolt_B5_17 "汇流排5单体平均电压";
CM_ SG_ 2335043233 M2P_BMS_Status_B5 "汇流排5能量状态";
CM_ SG_ 2335043233 M2P_SOC_B5 "汇流排5系统SOC";
CM_ SG_ 2335043233 M2P_SOH_B5 "汇流排5系统SOH";
CM_ SG_ 2335043233 Reserved_17 "预留";
CM_ SG_ 2335043234 M2P_SysMinVolt_B5_18 "汇流排5单体最小电压";
CM_ SG_ 2335043234 M2P_SysAvgVolt_B5_18 "汇流排5单体平均电压";
CM_ SG_ 2335043234 M2P_BMS_Status_B5 "汇流排5能量状态";
CM_ SG_ 2335043234 M2P_SOC_B5 "汇流排5系统SOC";
CM_ SG_ 2335043234 M2P_SOH_B5 "汇流排5系统SOH";
CM_ SG_ 2335043234 Reserved_18 "预留";
CM_ SG_ 2335043235 M2P_SysMinVolt_B5_19 "汇流排5单体最小电压";
CM_ SG_ 2335043235 M2P_SysAvgVolt_B5_19 "汇流排5单体平均电压";
CM_ SG_ 2335043235 M2P_BMS_Status_B5 "汇流排5能量状态";
CM_ SG_ 2335043235 M2P_SOC_B5 "汇流排5系统SOC";
CM_ SG_ 2335043235 M2P_SOH_B5 "汇流排5系统SOH";
CM_ SG_ 2335043235 Reserved_19 "预留";
CM_ SG_ 2335043236 M2P_SysMinVolt_B5_20 "汇流排5单体最小电压";
CM_ SG_ 2335043236 M2P_SysAvgVolt_B5_20 "汇流排5单体平均电压";
CM_ SG_ 2335043236 M2P_BMS_Status_B5 "汇流排5能量状态";
CM_ SG_ 2335043236 M2P_SOC_B5 "汇流排5系统SOC";
CM_ SG_ 2335043236 M2P_SOH_B5 "汇流排5系统SOH";
CM_ SG_ 2335043236 Reserved_20 "预留";
CM_ SG_ 2335043237 M2P_SysMinVolt_B5_21 "汇流排5单体最小电压";
CM_ SG_ 2335043237 M2P_SysAvgVolt_B5_21 "汇流排5单体平均电压";
CM_ SG_ 2335043237 M2P_BMS_Status_B5 "汇流排5能量状态";
CM_ SG_ 2335043237 M2P_SOC_B5 "汇流排5系统SOC";
CM_ SG_ 2335043237 M2P_SOH_B5 "汇流排5系统SOH";
CM_ SG_ 2335043237 Reserved_21 "预留";
CM_ SG_ 2335043238 M2P_SysMinVolt_B5_22 "汇流排5单体最小电压";
CM_ SG_ 2335043238 M2P_SysAvgVolt_B5_22 "汇流排5单体平均电压";
CM_ SG_ 2335043238 M2P_BMS_Status_B5 "汇流排5能量状态";
CM_ SG_ 2335043238 M2P_SOC_B5 "汇流排5系统SOC";
CM_ SG_ 2335043238 M2P_SOH_B5 "汇流排5系统SOH";
CM_ SG_ 2335043238 Reserved_22 "预留";
CM_ SG_ 2335043239 M2P_SysMinVolt_B5_23 "汇流排5单体最小电压";
CM_ SG_ 2335043239 M2P_SysAvgVolt_B5_23 "汇流排5单体平均电压";
CM_ SG_ 2335043239 M2P_BMS_Status_B5 "汇流排5能量状态";
CM_ SG_ 2335043239 M2P_SOC_B5 "汇流排5系统SOC";
CM_ SG_ 2335043239 M2P_SOH_B5 "汇流排5系统SOH";
CM_ SG_ 2335043239 Reserved_23 "预留";
CM_ SG_ 2335043240 M2P_SysMinVolt_B5_24 "汇流排5单体最小电压";
CM_ SG_ 2335043240 M2P_SysAvgVolt_B5_24 "汇流排5单体平均电压";
CM_ SG_ 2335043240 M2P_BMS_Status_B5 "汇流排5能量状态";
CM_ SG_ 2335043240 M2P_SOC_B5 "汇流排5系统SOC";
CM_ SG_ 2335043240 M2P_SOH_B5 "汇流排5系统SOH";
CM_ SG_ 2335043240 Reserved_24 "预留";
CM_ SG_ 2335043241 M2P_SysMinVolt_B5_25 "汇流排5单体最小电压";
CM_ SG_ 2335043241 M2P_SysAvgVolt_B5_25 "汇流排5单体平均电压";
CM_ SG_ 2335043241 M2P_BMS_Status_B5 "汇流排5能量状态";
CM_ SG_ 2335043241 M2P_SOC_B5 "汇流排5系统SOC";
CM_ SG_ 2335043241 M2P_SOH_B5 "汇流排5系统SOH";
CM_ SG_ 2335043241 Reserved_25 "预留";
CM_ SG_ 2335043242 M2P_SysMinVolt_B5_26 "汇流排5单体最小电压";
CM_ SG_ 2335043242 M2P_SysAvgVolt_B5_26 "汇流排5单体平均电压";
CM_ SG_ 2335043242 M2P_BMS_Status_B5 "汇流排5能量状态";
CM_ SG_ 2335043242 M2P_SOC_B5 "汇流排5系统SOC";
CM_ SG_ 2335043242 M2P_SOH_B5 "汇流排5系统SOH";
CM_ SG_ 2335043242 Reserved_26 "预留";
CM_ SG_ 2335043243 M2P_SysMinVolt_B5_27 "汇流排5单体最小电压";
CM_ SG_ 2335043243 M2P_SysAvgVolt_B5_27 "汇流排5单体平均电压";
CM_ SG_ 2335043243 M2P_BMS_Status_B5 "汇流排5能量状态";
CM_ SG_ 2335043243 M2P_SOC_B5 "汇流排5系统SOC";
CM_ SG_ 2335043243 M2P_SOH_B5 "汇流排5系统SOH";
CM_ SG_ 2335043243 Reserved_27 "预留";
CM_ SG_ 2335043244 M2P_SysMinVolt_B5_28 "汇流排5单体最小电压";
CM_ SG_ 2335043244 M2P_SysAvgVolt_B5_28 "汇流排5单体平均电压";
CM_ SG_ 2335043244 M2P_BMS_Status_B5 "汇流排5能量状态";
CM_ SG_ 2335043244 M2P_SOC_B5 "汇流排5系统SOC";
CM_ SG_ 2335043244 M2P_SOH_B5 "汇流排5系统SOH";
CM_ SG_ 2335043244 Reserved_28 "预留";
CM_ SG_ 2335043245 M2P_SysMinVolt_B5_29 "汇流排5单体最小电压";
CM_ SG_ 2335043245 M2P_SysAvgVolt_B5_29 "汇流排5单体平均电压";
CM_ SG_ 2335043245 M2P_BMS_Status_B5 "汇流排5能量状态";
CM_ SG_ 2335043245 M2P_SOC_B5 "汇流排5系统SOC";
CM_ SG_ 2335043245 M2P_SOH_B5 "汇流排5系统SOH";
CM_ SG_ 2335043245 Reserved_29 "预留";
CM_ SG_ 2335043246 M2P_SysMinVolt_B5_30 "汇流排5单体最小电压";
CM_ SG_ 2335043246 M2P_SysAvgVolt_B5_30 "汇流排5单体平均电压";
CM_ SG_ 2335043246 M2P_BMS_Status_B5 "汇流排5能量状态";
CM_ SG_ 2335043246 M2P_SOC_B5 "汇流排5系统SOC";
CM_ SG_ 2335043246 M2P_SOH_B5 "汇流排5系统SOH";
CM_ SG_ 2335043246 Reserved_30 "预留";
CM_ SG_ 2335043247 M2P_SysMinVolt_B5_31 "汇流排5单体最小电压";
CM_ SG_ 2335043247 M2P_SysAvgVolt_B5_31 "汇流排5单体平均电压";
CM_ SG_ 2335043247 M2P_BMS_Status_B5 "汇流排5能量状态";
CM_ SG_ 2335043247 M2P_SOC_B5 "汇流排5系统SOC";
CM_ SG_ 2335043247 M2P_SOH_B5 "汇流排5系统SOH";
CM_ SG_ 2335043247 Reserved_31 "预留";
CM_ SG_ 2335108753 M2P_SOE_Charge_B5 "汇流排5系可充电SOE";
CM_ SG_ 2335108753 M2P_SOE_Discharge_B5 "汇流排5系可放电SOE";
CM_ SG_ 2335108753 Reserved_01 "预留";
CM_ SG_ 2335108754 M2P_SOE_Charge_B5 "汇流排5系可充电SOE";
CM_ SG_ 2335108754 M2P_SOE_Discharge_B5 "汇流排5系可放电SOE";
CM_ SG_ 2335108754 Reserved_02 "预留";
CM_ SG_ 2335108755 M2P_SOE_Charge_B5 "汇流排5系可充电SOE";
CM_ SG_ 2335108755 M2P_SOE_Discharge_B5 "汇流排5系可放电SOE";
CM_ SG_ 2335108755 Reserved_03 "预留";
CM_ SG_ 2335108756 M2P_SOE_Charge_B5 "汇流排5系可充电SOE";
CM_ SG_ 2335108756 M2P_SOE_Discharge_B5 "汇流排5系可放电SOE";
CM_ SG_ 2335108756 Reserved_04 "预留";
CM_ SG_ 2335108757 M2P_SOE_Charge_B5 "汇流排5系可充电SOE";
CM_ SG_ 2335108757 M2P_SOE_Discharge_B5 "汇流排5系可放电SOE";
CM_ SG_ 2335108757 Reserved_05 "预留";
CM_ SG_ 2335108758 M2P_SOE_Charge_B5 "汇流排5系可充电SOE";
CM_ SG_ 2335108758 M2P_SOE_Discharge_B5 "汇流排5系可放电SOE";
CM_ SG_ 2335108758 Reserved_06 "预留";
CM_ SG_ 2335108759 M2P_SOE_Charge_B5 "汇流排5系可充电SOE";
CM_ SG_ 2335108759 M2P_SOE_Discharge_B5 "汇流排5系可放电SOE";
CM_ SG_ 2335108759 Reserved_07 "预留";
CM_ SG_ 2335108760 M2P_SOE_Charge_B5 "汇流排5系可充电SOE";
CM_ SG_ 2335108760 M2P_SOE_Discharge_B5 "汇流排5系可放电SOE";
CM_ SG_ 2335108760 Reserved_08 "预留";
CM_ SG_ 2335108761 M2P_SOE_Charge_B5 "汇流排5系可充电SOE";
CM_ SG_ 2335108761 M2P_SOE_Discharge_B5 "汇流排5系可放电SOE";
CM_ SG_ 2335108761 Reserved_09 "预留";
CM_ SG_ 2335108762 M2P_SOE_Charge_B5 "汇流排5系可充电SOE";
CM_ SG_ 2335108762 M2P_SOE_Discharge_B5 "汇流排5系可放电SOE";
CM_ SG_ 2335108762 Reserved_10 "预留";
CM_ SG_ 2335108763 M2P_SOE_Charge_B5 "汇流排5系可充电SOE";
CM_ SG_ 2335108763 M2P_SOE_Discharge_B5 "汇流排5系可放电SOE";
CM_ SG_ 2335108763 Reserved_11 "预留";
CM_ SG_ 2335108764 M2P_SOE_Charge_B5 "汇流排5系可充电SOE";
CM_ SG_ 2335108764 M2P_SOE_Discharge_B5 "汇流排5系可放电SOE";
CM_ SG_ 2335108764 Reserved_12 "预留";
CM_ SG_ 2335108765 M2P_SOE_Charge_B5 "汇流排5系可充电SOE";
CM_ SG_ 2335108765 M2P_SOE_Discharge_B5 "汇流排5系可放电SOE";
CM_ SG_ 2335108765 Reserved_13 "预留";
CM_ SG_ 2335108766 M2P_SOE_Charge_B5 "汇流排5系可充电SOE";
CM_ SG_ 2335108766 M2P_SOE_Discharge_B5 "汇流排5系可放电SOE";
CM_ SG_ 2335108766 Reserved_14 "预留";
CM_ SG_ 2335108767 M2P_SOE_Charge_B5 "汇流排5系可充电SOE";
CM_ SG_ 2335108767 M2P_SOE_Discharge_B5 "汇流排5系可放电SOE";
CM_ SG_ 2335108767 Reserved_15 "预留";
CM_ SG_ 2335108768 M2P_SOE_Charge_B5 "汇流排5系可充电SOE";
CM_ SG_ 2335108768 M2P_SOE_Discharge_B5 "汇流排5系可放电SOE";
CM_ SG_ 2335108768 Reserved_16 "预留";
CM_ SG_ 2335108769 M2P_SOE_Charge_B5 "汇流排5系可充电SOE";
CM_ SG_ 2335108769 M2P_SOE_Discharge_B5 "汇流排5系可放电SOE";
CM_ SG_ 2335108769 Reserved_17 "预留";
CM_ SG_ 2335108770 M2P_SOE_Charge_B5 "汇流排5系可充电SOE";
CM_ SG_ 2335108770 M2P_SOE_Discharge_B5 "汇流排5系可放电SOE";
CM_ SG_ 2335108770 Reserved_18 "预留";
CM_ SG_ 2335108771 M2P_SOE_Charge_B5 "汇流排5系可充电SOE";
CM_ SG_ 2335108771 M2P_SOE_Discharge_B5 "汇流排5系可放电SOE";
CM_ SG_ 2335108771 Reserved_19 "预留";
CM_ SG_ 2335108772 M2P_SOE_Charge_B5 "汇流排5系可充电SOE";
CM_ SG_ 2335108772 M2P_SOE_Discharge_B5 "汇流排5系可放电SOE";
CM_ SG_ 2335108772 Reserved_20 "预留";
CM_ SG_ 2335108773 M2P_SOE_Charge_B5 "汇流排5系可充电SOE";
CM_ SG_ 2335108773 M2P_SOE_Discharge_B5 "汇流排5系可放电SOE";
CM_ SG_ 2335108773 Reserved_21 "预留";
CM_ SG_ 2335108774 M2P_SOE_Charge_B5 "汇流排5系可充电SOE";
CM_ SG_ 2335108774 M2P_SOE_Discharge_B5 "汇流排5系可放电SOE";
CM_ SG_ 2335108774 Reserved_22 "预留";
CM_ SG_ 2335108775 M2P_SOE_Charge_B5 "汇流排5系可充电SOE";
CM_ SG_ 2335108775 M2P_SOE_Discharge_B5 "汇流排5系可放电SOE";
CM_ SG_ 2335108775 Reserved_23 "预留";
CM_ SG_ 2335108776 M2P_SOE_Charge_B5 "汇流排5系可充电SOE";
CM_ SG_ 2335108776 M2P_SOE_Discharge_B5 "汇流排5系可放电SOE";
CM_ SG_ 2335108776 Reserved_24 "预留";
CM_ SG_ 2335108777 M2P_SOE_Charge_B5 "汇流排5系可充电SOE";
CM_ SG_ 2335108777 M2P_SOE_Discharge_B5 "汇流排5系可放电SOE";
CM_ SG_ 2335108777 Reserved_25 "预留";
CM_ SG_ 2335108778 M2P_SOE_Charge_B5 "汇流排5系可充电SOE";
CM_ SG_ 2335108778 M2P_SOE_Discharge_B5 "汇流排5系可放电SOE";
CM_ SG_ 2335108778 Reserved_26 "预留";
CM_ SG_ 2335108779 M2P_SOE_Charge_B5 "汇流排5系可充电SOE";
CM_ SG_ 2335108779 M2P_SOE_Discharge_B5 "汇流排5系可放电SOE";
CM_ SG_ 2335108779 Reserved_27 "预留";
CM_ SG_ 2335108780 M2P_SOE_Charge_B5 "汇流排5系可充电SOE";
CM_ SG_ 2335108780 M2P_SOE_Discharge_B5 "汇流排5系可放电SOE";
CM_ SG_ 2335108780 Reserved_28 "预留";
CM_ SG_ 2335108781 M2P_SOE_Charge_B5 "汇流排5系可充电SOE";
CM_ SG_ 2335108781 M2P_SOE_Discharge_B5 "汇流排5系可放电SOE";
CM_ SG_ 2335108781 Reserved_29 "预留";
CM_ SG_ 2335108782 M2P_SOE_Charge_B5 "汇流排5系可充电SOE";
CM_ SG_ 2335108782 M2P_SOE_Discharge_B5 "汇流排5系可放电SOE";
CM_ SG_ 2335108782 Reserved_30 "预留";
CM_ SG_ 2335108783 M2P_SOE_Charge_B5 "汇流排5系可充电SOE";
CM_ SG_ 2335108783 M2P_SOE_Discharge_B5 "汇流排5系可放电SOE";
CM_ SG_ 2335108783 Reserved_31 "预留";
CM_ SG_ 2335174289 M2P_Measure_Vol_B6_01 "汇流排6所有高压在线电柜外侧电压平均值    ";
CM_ SG_ 2335174289 M2P_Current_B6_01 "汇流排6所有电柜电流累加和";
CM_ SG_ 2335174289 M2P_PermitMaxCharge_I_B6_01 "汇流排6最大允许充电电流";
CM_ SG_ 2335174289 M2P_PermitMaxDisCharge_I_B6_01 "汇流排6最大允许放电电流";
CM_ SG_ 2335174290 M2P_Measure_Vol_B6_02 "汇流排6所有高压在线电柜外侧电压平均值    ";
CM_ SG_ 2335174290 M2P_Current_B6_02 "汇流排6所有电柜电流累加和";
CM_ SG_ 2335174290 M2P_PermitMaxCharge_I_B6_02 "汇流排6最大允许充电电流";
CM_ SG_ 2335174290 M2P_PermitMaxDisCharge_I_B6_02 "汇流排6最大允许放电电流";
CM_ SG_ 2335174291 M2P_Measure_Vol_B6_03 "汇流排6所有高压在线电柜外侧电压平均值    ";
CM_ SG_ 2335174291 M2P_Current_B6_03 "汇流排6所有电柜电流累加和";
CM_ SG_ 2335174291 M2P_PermitMaxCharge_I_B6_03 "汇流排6最大允许充电电流";
CM_ SG_ 2335174291 M2P_PermitMaxDisCharge_I_B6_03 "汇流排6最大允许放电电流";
CM_ SG_ 2335174292 M2P_Measure_Vol_B6_04 "汇流排6所有高压在线电柜外侧电压平均值    ";
CM_ SG_ 2335174292 M2P_Current_B6_04 "汇流排6所有电柜电流累加和";
CM_ SG_ 2335174292 M2P_PermitMaxCharge_I_B6_04 "汇流排6最大允许充电电流";
CM_ SG_ 2335174292 M2P_PermitMaxDisCharge_I_B6_04 "汇流排6最大允许放电电流";
CM_ SG_ 2335174293 M2P_Measure_Vol_B6_05 "汇流排6所有高压在线电柜外侧电压平均值    ";
CM_ SG_ 2335174293 M2P_Current_B6_05 "汇流排6所有电柜电流累加和";
CM_ SG_ 2335174293 M2P_PermitMaxCharge_I_B6_05 "汇流排6最大允许充电电流";
CM_ SG_ 2335174293 M2P_PermitMaxDisCharge_I_B6_05 "汇流排6最大允许放电电流";
CM_ SG_ 2335174294 M2P_Measure_Vol_B6_06 "汇流排6所有高压在线电柜外侧电压平均值    ";
CM_ SG_ 2335174294 M2P_Current_B6_06 "汇流排6所有电柜电流累加和";
CM_ SG_ 2335174294 M2P_PermitMaxCharge_I_B6_06 "汇流排6最大允许充电电流";
CM_ SG_ 2335174294 M2P_PermitMaxDisCharge_I_B6_06 "汇流排6最大允许放电电流";
CM_ SG_ 2335174295 M2P_Measure_Vol_B6_07 "汇流排6所有高压在线电柜外侧电压平均值    ";
CM_ SG_ 2335174295 M2P_Current_B6_07 "汇流排6所有电柜电流累加和";
CM_ SG_ 2335174295 M2P_PermitMaxCharge_I_B6_07 "汇流排6最大允许充电电流";
CM_ SG_ 2335174295 M2P_PermitMaxDisCharge_I_B6_07 "汇流排6最大允许放电电流";
CM_ SG_ 2335174296 M2P_Measure_Vol_B6_08 "汇流排6所有高压在线电柜外侧电压平均值    ";
CM_ SG_ 2335174296 M2P_Current_B6_08 "汇流排6所有电柜电流累加和";
CM_ SG_ 2335174296 M2P_PermitMaxCharge_I_B6_08 "汇流排6最大允许充电电流";
CM_ SG_ 2335174296 M2P_PermitMaxDisCharge_I_B6_08 "汇流排6最大允许放电电流";
CM_ SG_ 2335174297 M2P_Measure_Vol_B6_09 "汇流排6所有高压在线电柜外侧电压平均值    ";
CM_ SG_ 2335174297 M2P_Current_B6_09 "汇流排6所有电柜电流累加和";
CM_ SG_ 2335174297 M2P_PermitMaxCharge_I_B6_09 "汇流排6最大允许充电电流";
CM_ SG_ 2335174297 M2P_PermitMaxDisCharge_I_B6_09 "汇流排6最大允许放电电流";
CM_ SG_ 2335174298 M2P_Measure_Vol_B6_10 "汇流排6所有高压在线电柜外侧电压平均值    ";
CM_ SG_ 2335174298 M2P_Current_B6_10 "汇流排6所有电柜电流累加和";
CM_ SG_ 2335174298 M2P_PermitMaxCharge_I_B6_10 "汇流排6最大允许充电电流";
CM_ SG_ 2335174298 M2P_PermitMaxDisCharge_I_B6_10 "汇流排6最大允许放电电流";
CM_ SG_ 2335174299 M2P_Measure_Vol_B6_11 "汇流排6所有高压在线电柜外侧电压平均值    ";
CM_ SG_ 2335174299 M2P_Current_B6_11 "汇流排6所有电柜电流累加和";
CM_ SG_ 2335174299 M2P_PermitMaxCharge_I_B6_11 "汇流排6最大允许充电电流";
CM_ SG_ 2335174299 M2P_PermitMaxDisCharge_I_B6_11 "汇流排6最大允许放电电流";
CM_ SG_ 2335174300 M2P_Measure_Vol_B6_12 "汇流排6所有高压在线电柜外侧电压平均值    ";
CM_ SG_ 2335174300 M2P_Current_B6_12 "汇流排6所有电柜电流累加和";
CM_ SG_ 2335174300 M2P_PermitMaxCharge_I_B6_12 "汇流排6最大允许充电电流";
CM_ SG_ 2335174300 M2P_PermitMaxDisCharge_I_B6_12 "汇流排6最大允许放电电流";
CM_ SG_ 2335174301 M2P_Measure_Vol_B6_13 "汇流排6所有高压在线电柜外侧电压平均值    ";
CM_ SG_ 2335174301 M2P_Current_B6_13 "汇流排6所有电柜电流累加和";
CM_ SG_ 2335174301 M2P_PermitMaxCharge_I_B6_13 "汇流排6最大允许充电电流";
CM_ SG_ 2335174301 M2P_PermitMaxDisCharge_I_B6_13 "汇流排6最大允许放电电流";
CM_ SG_ 2335174302 M2P_Measure_Vol_B6_14 "汇流排6所有高压在线电柜外侧电压平均值    ";
CM_ SG_ 2335174302 M2P_Current_B6_14 "汇流排6所有电柜电流累加和";
CM_ SG_ 2335174302 M2P_PermitMaxCharge_I_B6_14 "汇流排6最大允许充电电流";
CM_ SG_ 2335174302 M2P_PermitMaxDisCharge_I_B6_14 "汇流排6最大允许放电电流";
CM_ SG_ 2335174303 M2P_Measure_Vol_B6_15 "汇流排6所有高压在线电柜外侧电压平均值    ";
CM_ SG_ 2335174303 M2P_Current_B6_15 "汇流排6所有电柜电流累加和";
CM_ SG_ 2335174303 M2P_PermitMaxCharge_I_B6_15 "汇流排6最大允许充电电流";
CM_ SG_ 2335174303 M2P_PermitMaxDisCharge_I_B6_15 "汇流排6最大允许放电电流";
CM_ SG_ 2335174304 M2P_Measure_Vol_B6_16 "汇流排6所有高压在线电柜外侧电压平均值    ";
CM_ SG_ 2335174304 M2P_Current_B6_16 "汇流排6所有电柜电流累加和";
CM_ SG_ 2335174304 M2P_PermitMaxCharge_I_B6_16 "汇流排6最大允许充电电流";
CM_ SG_ 2335174304 M2P_PermitMaxDisCharge_I_B6_16 "汇流排6最大允许放电电流";
CM_ SG_ 2335174305 M2P_Measure_Vol_B6_17 "汇流排6所有高压在线电柜外侧电压平均值    ";
CM_ SG_ 2335174305 M2P_Current_B6_17 "汇流排6所有电柜电流累加和";
CM_ SG_ 2335174305 M2P_PermitMaxCharge_I_B6_17 "汇流排6最大允许充电电流";
CM_ SG_ 2335174305 M2P_PermitMaxDisCharge_I_B6_17 "汇流排6最大允许放电电流";
CM_ SG_ 2335174306 M2P_Measure_Vol_B6_18 "汇流排6所有高压在线电柜外侧电压平均值    ";
CM_ SG_ 2335174306 M2P_Current_B6_18 "汇流排6所有电柜电流累加和";
CM_ SG_ 2335174306 M2P_PermitMaxCharge_I_B6_18 "汇流排6最大允许充电电流";
CM_ SG_ 2335174306 M2P_PermitMaxDisCharge_I_B6_18 "汇流排6最大允许放电电流";
CM_ SG_ 2335174307 M2P_Measure_Vol_B6_19 "汇流排6所有高压在线电柜外侧电压平均值    ";
CM_ SG_ 2335174307 M2P_Current_B6_19 "汇流排6所有电柜电流累加和";
CM_ SG_ 2335174307 M2P_PermitMaxCharge_I_B6_19 "汇流排6最大允许充电电流";
CM_ SG_ 2335174307 M2P_PermitMaxDisCharge_I_B6_19 "汇流排6最大允许放电电流";
CM_ SG_ 2335174308 M2P_Measure_Vol_B6_20 "汇流排6所有高压在线电柜外侧电压平均值    ";
CM_ SG_ 2335174308 M2P_Current_B6_20 "汇流排6所有电柜电流累加和";
CM_ SG_ 2335174308 M2P_PermitMaxCharge_I_B6_20 "汇流排6最大允许充电电流";
CM_ SG_ 2335174308 M2P_PermitMaxDisCharge_I_B6_20 "汇流排6最大允许放电电流";
CM_ SG_ 2335174309 M2P_Measure_Vol_B6_21 "汇流排6所有高压在线电柜外侧电压平均值    ";
CM_ SG_ 2335174309 M2P_Current_B6_21 "汇流排6所有电柜电流累加和";
CM_ SG_ 2335174309 M2P_PermitMaxCharge_I_B6_21 "汇流排6最大允许充电电流";
CM_ SG_ 2335174309 M2P_PermitMaxDisCharge_I_B6_21 "汇流排6最大允许放电电流";
CM_ SG_ 2335174310 M2P_Measure_Vol_B6_22 "汇流排6所有高压在线电柜外侧电压平均值    ";
CM_ SG_ 2335174310 M2P_Current_B6_22 "汇流排6所有电柜电流累加和";
CM_ SG_ 2335174310 M2P_PermitMaxCharge_I_B6_22 "汇流排6最大允许充电电流";
CM_ SG_ 2335174310 M2P_PermitMaxDisCharge_I_B6_22 "汇流排6最大允许放电电流";
CM_ SG_ 2335174311 M2P_Measure_Vol_B6_23 "汇流排6所有高压在线电柜外侧电压平均值    ";
CM_ SG_ 2335174311 M2P_Current_B6_23 "汇流排6所有电柜电流累加和";
CM_ SG_ 2335174311 M2P_PermitMaxCharge_I_B6_23 "汇流排6最大允许充电电流";
CM_ SG_ 2335174311 M2P_PermitMaxDisCharge_I_B6_23 "汇流排6最大允许放电电流";
CM_ SG_ 2335174312 M2P_Measure_Vol_B6_24 "汇流排6所有高压在线电柜外侧电压平均值    ";
CM_ SG_ 2335174312 M2P_Current_B6_24 "汇流排6所有电柜电流累加和";
CM_ SG_ 2335174312 M2P_PermitMaxCharge_I_B6_24 "汇流排6最大允许充电电流";
CM_ SG_ 2335174312 M2P_PermitMaxDisCharge_I_B6_24 "汇流排6最大允许放电电流";
CM_ SG_ 2335174313 M2P_Measure_Vol_B6_25 "汇流排6所有高压在线电柜外侧电压平均值    ";
CM_ SG_ 2335174313 M2P_Current_B6_25 "汇流排6所有电柜电流累加和";
CM_ SG_ 2335174313 M2P_PermitMaxCharge_I_B6_25 "汇流排6最大允许充电电流";
CM_ SG_ 2335174313 M2P_PermitMaxDisCharge_I_B6_25 "汇流排6最大允许放电电流";
CM_ SG_ 2335174314 M2P_Measure_Vol_B6_26 "汇流排6所有高压在线电柜外侧电压平均值    ";
CM_ SG_ 2335174314 M2P_Current_B6_26 "汇流排6所有电柜电流累加和";
CM_ SG_ 2335174314 M2P_PermitMaxCharge_I_B6_26 "汇流排6最大允许充电电流";
CM_ SG_ 2335174314 M2P_PermitMaxDisCharge_I_B6_26 "汇流排6最大允许放电电流";
CM_ SG_ 2335174315 M2P_Measure_Vol_B6_27 "汇流排6所有高压在线电柜外侧电压平均值    ";
CM_ SG_ 2335174315 M2P_Current_B6_27 "汇流排6所有电柜电流累加和";
CM_ SG_ 2335174315 M2P_PermitMaxCharge_I_B6_27 "汇流排6最大允许充电电流";
CM_ SG_ 2335174315 M2P_PermitMaxDisCharge_I_B6_27 "汇流排6最大允许放电电流";
CM_ SG_ 2335174316 M2P_Measure_Vol_B6_28 "汇流排6所有高压在线电柜外侧电压平均值    ";
CM_ SG_ 2335174316 M2P_Current_B6_28 "汇流排6所有电柜电流累加和";
CM_ SG_ 2335174316 M2P_PermitMaxCharge_I_B6_28 "汇流排6最大允许充电电流";
CM_ SG_ 2335174316 M2P_PermitMaxDisCharge_I_B6_28 "汇流排6最大允许放电电流";
CM_ SG_ 2335174317 M2P_Measure_Vol_B6_29 "汇流排6所有高压在线电柜外侧电压平均值    ";
CM_ SG_ 2335174317 M2P_Current_B6_29 "汇流排6所有电柜电流累加和";
CM_ SG_ 2335174317 M2P_PermitMaxCharge_I_B6_29 "汇流排6最大允许充电电流";
CM_ SG_ 2335174317 M2P_PermitMaxDisCharge_I_B6_29 "汇流排6最大允许放电电流";
CM_ SG_ 2335174318 M2P_Measure_Vol_B6_30 "汇流排6所有高压在线电柜外侧电压平均值    ";
CM_ SG_ 2335174318 M2P_Current_B6_30 "汇流排6所有电柜电流累加和";
CM_ SG_ 2335174318 M2P_PermitMaxCharge_I_B6_30 "汇流排6最大允许充电电流";
CM_ SG_ 2335174318 M2P_PermitMaxDisCharge_I_B6_30 "汇流排6最大允许放电电流";
CM_ SG_ 2335174319 M2P_Measure_Vol_B6_31 "汇流排6所有高压在线电柜外侧电压平均值    ";
CM_ SG_ 2335174319 M2P_Current_B6_31 "汇流排6所有电柜电流累加和";
CM_ SG_ 2335174319 M2P_PermitMaxCharge_I_B6_31 "汇流排6最大允许充电电流";
CM_ SG_ 2335174319 M2P_PermitMaxDisCharge_I_B6_31 "汇流排6最大允许放电电流";
CM_ SG_ 2335239825 M2P_PermitMaxVolt_B6_01 "汇流排6最高允许充电电压 （配置量）";
CM_ SG_ 2335239825 M2P_PermitMinVolt_B6_01 "汇流排6最低允许放电电压 （配置量）";
CM_ SG_ 2335239825 M2P_PermitMaxPow_Chg_B6_01 "汇流排6最大允许充电功率";
CM_ SG_ 2335239825 M2P_PermitMaxPow_DisChg_B6_01 "汇流排6最大允许放电功率";
CM_ SG_ 2335239826 M2P_PermitMaxVolt_B6_02 "汇流排6最高允许充电电压 （配置量）";
CM_ SG_ 2335239826 M2P_PermitMinVolt_B6_02 "汇流排6最低允许放电电压 （配置量）";
CM_ SG_ 2335239826 M2P_PermitMaxPow_Chg_B6_02 "汇流排6最大允许充电功率";
CM_ SG_ 2335239826 M2P_PermitMaxPow_DisChg_B6_02 "汇流排6最大允许放电功率";
CM_ SG_ 2335239827 M2P_PermitMaxVolt_B6_03 "汇流排6最高允许充电电压 （配置量）";
CM_ SG_ 2335239827 M2P_PermitMinVolt_B6_03 "汇流排6最低允许放电电压 （配置量）";
CM_ SG_ 2335239827 M2P_PermitMaxPow_Chg_B6_03 "汇流排6最大允许充电功率";
CM_ SG_ 2335239827 M2P_PermitMaxPow_DisChg_B6_03 "汇流排6最大允许放电功率";
CM_ SG_ 2335239828 M2P_PermitMaxVolt_B6_04 "汇流排6最高允许充电电压 （配置量）";
CM_ SG_ 2335239828 M2P_PermitMinVolt_B6_04 "汇流排6最低允许放电电压 （配置量）";
CM_ SG_ 2335239828 M2P_PermitMaxPow_Chg_B6_04 "汇流排6最大允许充电功率";
CM_ SG_ 2335239828 M2P_PermitMaxPow_DisChg_B6_04 "汇流排6最大允许放电功率";
CM_ SG_ 2335239829 M2P_PermitMaxVolt_B6_05 "汇流排6最高允许充电电压 （配置量）";
CM_ SG_ 2335239829 M2P_PermitMinVolt_B6_05 "汇流排6最低允许放电电压 （配置量）";
CM_ SG_ 2335239829 M2P_PermitMaxPow_Chg_B6_05 "汇流排6最大允许充电功率";
CM_ SG_ 2335239829 M2P_PermitMaxPow_DisChg_B6_05 "汇流排6最大允许放电功率";
CM_ SG_ 2335239830 M2P_PermitMaxVolt_B6_06 "汇流排6最高允许充电电压 （配置量）";
CM_ SG_ 2335239830 M2P_PermitMinVolt_B6_06 "汇流排6最低允许放电电压 （配置量）";
CM_ SG_ 2335239830 M2P_PermitMaxPow_Chg_B6_06 "汇流排6最大允许充电功率";
CM_ SG_ 2335239830 M2P_PermitMaxPow_DisChg_B6_06 "汇流排6最大允许放电功率";
CM_ SG_ 2335239831 M2P_PermitMaxVolt_B6_07 "汇流排6最高允许充电电压 （配置量）";
CM_ SG_ 2335239831 M2P_PermitMinVolt_B6_07 "汇流排6最低允许放电电压 （配置量）";
CM_ SG_ 2335239831 M2P_PermitMaxPow_Chg_B6_07 "汇流排6最大允许充电功率";
CM_ SG_ 2335239831 M2P_PermitMaxPow_DisChg_B6_07 "汇流排6最大允许放电功率";
CM_ SG_ 2335239832 M2P_PermitMaxVolt_B6_08 "汇流排6最高允许充电电压 （配置量）";
CM_ SG_ 2335239832 M2P_PermitMinVolt_B6_08 "汇流排6最低允许放电电压 （配置量）";
CM_ SG_ 2335239832 M2P_PermitMaxPow_Chg_B6_08 "汇流排6最大允许充电功率";
CM_ SG_ 2335239832 M2P_PermitMaxPow_DisChg_B6_08 "汇流排6最大允许放电功率";
CM_ SG_ 2335239833 M2P_PermitMaxVolt_B6_09 "汇流排6最高允许充电电压 （配置量）";
CM_ SG_ 2335239833 M2P_PermitMinVolt_B6_09 "汇流排6最低允许放电电压 （配置量）";
CM_ SG_ 2335239833 M2P_PermitMaxPow_Chg_B6_09 "汇流排6最大允许充电功率";
CM_ SG_ 2335239833 M2P_PermitMaxPow_DisChg_B6_09 "汇流排6最大允许放电功率";
CM_ SG_ 2335239834 M2P_PermitMaxVolt_B6_10 "汇流排6最高允许充电电压 （配置量）";
CM_ SG_ 2335239834 M2P_PermitMinVolt_B6_10 "汇流排6最低允许放电电压 （配置量）";
CM_ SG_ 2335239834 M2P_PermitMaxPow_Chg_B6_10 "汇流排6最大允许充电功率";
CM_ SG_ 2335239834 M2P_PermitMaxPow_DisChg_B6_10 "汇流排6最大允许放电功率";
CM_ SG_ 2335239835 M2P_PermitMaxVolt_B6_11 "汇流排6最高允许充电电压 （配置量）";
CM_ SG_ 2335239835 M2P_PermitMinVolt_B6_11 "汇流排6最低允许放电电压 （配置量）";
CM_ SG_ 2335239835 M2P_PermitMaxPow_Chg_B6_11 "汇流排6最大允许充电功率";
CM_ SG_ 2335239835 M2P_PermitMaxPow_DisChg_B6_11 "汇流排6最大允许放电功率";
CM_ SG_ 2335239836 M2P_PermitMaxVolt_B6_12 "汇流排6最高允许充电电压 （配置量）";
CM_ SG_ 2335239836 M2P_PermitMinVolt_B6_12 "汇流排6最低允许放电电压 （配置量）";
CM_ SG_ 2335239836 M2P_PermitMaxPow_Chg_B6_12 "汇流排6最大允许充电功率";
CM_ SG_ 2335239836 M2P_PermitMaxPow_DisChg_B6_12 "汇流排6最大允许放电功率";
CM_ SG_ 2335239837 M2P_PermitMaxVolt_B6_13 "汇流排6最高允许充电电压 （配置量）";
CM_ SG_ 2335239837 M2P_PermitMinVolt_B6_13 "汇流排6最低允许放电电压 （配置量）";
CM_ SG_ 2335239837 M2P_PermitMaxPow_Chg_B6_13 "汇流排6最大允许充电功率";
CM_ SG_ 2335239837 M2P_PermitMaxPow_DisChg_B6_13 "汇流排6最大允许放电功率";
CM_ SG_ 2335239838 M2P_PermitMaxVolt_B6_14 "汇流排6最高允许充电电压 （配置量）";
CM_ SG_ 2335239838 M2P_PermitMinVolt_B6_14 "汇流排6最低允许放电电压 （配置量）";
CM_ SG_ 2335239838 M2P_PermitMaxPow_Chg_B6_14 "汇流排6最大允许充电功率";
CM_ SG_ 2335239838 M2P_PermitMaxPow_DisChg_B6_14 "汇流排6最大允许放电功率";
CM_ SG_ 2335239839 M2P_PermitMaxVolt_B6_15 "汇流排6最高允许充电电压 （配置量）";
CM_ SG_ 2335239839 M2P_PermitMinVolt_B6_15 "汇流排6最低允许放电电压 （配置量）";
CM_ SG_ 2335239839 M2P_PermitMaxPow_Chg_B6_15 "汇流排6最大允许充电功率";
CM_ SG_ 2335239839 M2P_PermitMaxPow_DisChg_B6_15 "汇流排6最大允许放电功率";
CM_ SG_ 2335239840 M2P_PermitMaxVolt_B6_16 "汇流排6最高允许充电电压 （配置量）";
CM_ SG_ 2335239840 M2P_PermitMinVolt_B6_16 "汇流排6最低允许放电电压 （配置量）";
CM_ SG_ 2335239840 M2P_PermitMaxPow_Chg_B6_16 "汇流排6最大允许充电功率";
CM_ SG_ 2335239840 M2P_PermitMaxPow_DisChg_B6_16 "汇流排6最大允许放电功率";
CM_ SG_ 2335239841 M2P_PermitMaxVolt_B6_17 "汇流排6最高允许充电电压 （配置量）";
CM_ SG_ 2335239841 M2P_PermitMinVolt_B6_17 "汇流排6最低允许放电电压 （配置量）";
CM_ SG_ 2335239841 M2P_PermitMaxPow_Chg_B6_17 "汇流排6最大允许充电功率";
CM_ SG_ 2335239841 M2P_PermitMaxPow_DisChg_B6_17 "汇流排6最大允许放电功率";
CM_ SG_ 2335239842 M2P_PermitMaxVolt_B6_18 "汇流排6最高允许充电电压 （配置量）";
CM_ SG_ 2335239842 M2P_PermitMinVolt_B6_18 "汇流排6最低允许放电电压 （配置量）";
CM_ SG_ 2335239842 M2P_PermitMaxPow_Chg_B6_18 "汇流排6最大允许充电功率";
CM_ SG_ 2335239842 M2P_PermitMaxPow_DisChg_B6_18 "汇流排6最大允许放电功率";
CM_ SG_ 2335239843 M2P_PermitMaxVolt_B6_19 "汇流排6最高允许充电电压 （配置量）";
CM_ SG_ 2335239843 M2P_PermitMinVolt_B6_19 "汇流排6最低允许放电电压 （配置量）";
CM_ SG_ 2335239843 M2P_PermitMaxPow_Chg_B6_19 "汇流排6最大允许充电功率";
CM_ SG_ 2335239843 M2P_PermitMaxPow_DisChg_B6_19 "汇流排6最大允许放电功率";
CM_ SG_ 2335239844 M2P_PermitMaxVolt_B6_20 "汇流排6最高允许充电电压 （配置量）";
CM_ SG_ 2335239844 M2P_PermitMinVolt_B6_20 "汇流排6最低允许放电电压 （配置量）";
CM_ SG_ 2335239844 M2P_PermitMaxPow_Chg_B6_20 "汇流排6最大允许充电功率";
CM_ SG_ 2335239844 M2P_PermitMaxPow_DisChg_B6_20 "汇流排6最大允许放电功率";
CM_ SG_ 2335239845 M2P_PermitMaxVolt_B6_21 "汇流排6最高允许充电电压 （配置量）";
CM_ SG_ 2335239845 M2P_PermitMinVolt_B6_21 "汇流排6最低允许放电电压 （配置量）";
CM_ SG_ 2335239845 M2P_PermitMaxPow_Chg_B6_21 "汇流排6最大允许充电功率";
CM_ SG_ 2335239845 M2P_PermitMaxPow_DisChg_B6_21 "汇流排6最大允许放电功率";
CM_ SG_ 2335239846 M2P_PermitMaxVolt_B6_22 "汇流排6最高允许充电电压 （配置量）";
CM_ SG_ 2335239846 M2P_PermitMinVolt_B6_22 "汇流排6最低允许放电电压 （配置量）";
CM_ SG_ 2335239846 M2P_PermitMaxPow_Chg_B6_22 "汇流排6最大允许充电功率";
CM_ SG_ 2335239846 M2P_PermitMaxPow_DisChg_B6_22 "汇流排6最大允许放电功率";
CM_ SG_ 2335239847 M2P_PermitMaxVolt_B6_23 "汇流排6最高允许充电电压 （配置量）";
CM_ SG_ 2335239847 M2P_PermitMinVolt_B6_23 "汇流排6最低允许放电电压 （配置量）";
CM_ SG_ 2335239847 M2P_PermitMaxPow_Chg_B6_23 "汇流排6最大允许充电功率";
CM_ SG_ 2335239847 M2P_PermitMaxPow_DisChg_B6_23 "汇流排6最大允许放电功率";
CM_ SG_ 2335239848 M2P_PermitMaxVolt_B6_24 "汇流排6最高允许充电电压 （配置量）";
CM_ SG_ 2335239848 M2P_PermitMinVolt_B6_24 "汇流排6最低允许放电电压 （配置量）";
CM_ SG_ 2335239848 M2P_PermitMaxPow_Chg_B6_24 "汇流排6最大允许充电功率";
CM_ SG_ 2335239848 M2P_PermitMaxPow_DisChg_B6_24 "汇流排6最大允许放电功率";
CM_ SG_ 2335239849 M2P_PermitMaxVolt_B6_25 "汇流排6最高允许充电电压 （配置量）";
CM_ SG_ 2335239849 M2P_PermitMinVolt_B6_25 "汇流排6最低允许放电电压 （配置量）";
CM_ SG_ 2335239849 M2P_PermitMaxPow_Chg_B6_25 "汇流排6最大允许充电功率";
CM_ SG_ 2335239849 M2P_PermitMaxPow_DisChg_B6_25 "汇流排6最大允许放电功率";
CM_ SG_ 2335239850 M2P_PermitMaxVolt_B6_26 "汇流排6最高允许充电电压 （配置量）";
CM_ SG_ 2335239850 M2P_PermitMinVolt_B6_26 "汇流排6最低允许放电电压 （配置量）";
CM_ SG_ 2335239850 M2P_PermitMaxPow_Chg_B6_26 "汇流排6最大允许充电功率";
CM_ SG_ 2335239850 M2P_PermitMaxPow_DisChg_B6_26 "汇流排6最大允许放电功率";
CM_ SG_ 2335239851 M2P_PermitMaxVolt_B6_27 "汇流排6最高允许充电电压 （配置量）";
CM_ SG_ 2335239851 M2P_PermitMinVolt_B6_27 "汇流排6最低允许放电电压 （配置量）";
CM_ SG_ 2335239851 M2P_PermitMaxPow_Chg_B6_27 "汇流排6最大允许充电功率";
CM_ SG_ 2335239851 M2P_PermitMaxPow_DisChg_B6_27 "汇流排6最大允许放电功率";
CM_ SG_ 2335239852 M2P_PermitMaxVolt_B6_28 "汇流排6最高允许充电电压 （配置量）";
CM_ SG_ 2335239852 M2P_PermitMinVolt_B6_28 "汇流排6最低允许放电电压 （配置量）";
CM_ SG_ 2335239852 M2P_PermitMaxPow_Chg_B6_28 "汇流排6最大允许充电功率";
CM_ SG_ 2335239852 M2P_PermitMaxPow_DisChg_B6_28 "汇流排6最大允许放电功率";
CM_ SG_ 2335239853 M2P_PermitMaxVolt_B6_29 "汇流排6最高允许充电电压 （配置量）";
CM_ SG_ 2335239853 M2P_PermitMinVolt_B6_29 "汇流排6最低允许放电电压 （配置量）";
CM_ SG_ 2335239853 M2P_PermitMaxPow_Chg_B6_29 "汇流排6最大允许充电功率";
CM_ SG_ 2335239853 M2P_PermitMaxPow_DisChg_B6_29 "汇流排6最大允许放电功率";
CM_ SG_ 2335239854 M2P_PermitMaxVolt_B6_30 "汇流排6最高允许充电电压 （配置量）";
CM_ SG_ 2335239854 M2P_PermitMinVolt_B6_30 "汇流排6最低允许放电电压 （配置量）";
CM_ SG_ 2335239854 M2P_PermitMaxPow_Chg_B6_30 "汇流排6最大允许充电功率";
CM_ SG_ 2335239854 M2P_PermitMaxPow_DisChg_B6_30 "汇流排6最大允许放电功率";
CM_ SG_ 2335239855 M2P_PermitMaxVolt_B6_31 "汇流排6最高允许充电电压 （配置量）";
CM_ SG_ 2335239855 M2P_PermitMinVolt_B6_31 "汇流排6最低允许放电电压 （配置量）";
CM_ SG_ 2335239855 M2P_PermitMaxPow_Chg_B6_31 "汇流排6最大允许充电功率";
CM_ SG_ 2335239855 M2P_PermitMaxPow_DisChg_B6_31 "汇流排6最大允许放电功率";
CM_ SG_ 2335305361 M2P_Power_B6_01 "汇流排6实时功率";
CM_ SG_ 2335305361 M2P_SysremEngy_Chg_B6_01 "汇流排6充电剩余能量";
CM_ SG_ 2335305361 M2P_SysremEngy_DisChg_B6_01 "汇流排6放电剩余能量";
CM_ SG_ 2335305361 M2P_SysMaxVolt_B6_01 "汇流排6单体最大电压  ";
CM_ SG_ 2335305362 M2P_Power_B6_02 "汇流排6实时功率";
CM_ SG_ 2335305362 M2P_SysremEngy_Chg_B6_02 "汇流排6充电剩余能量";
CM_ SG_ 2335305362 M2P_SysremEngy_DisChg_B6_02 "汇流排6放电剩余能量";
CM_ SG_ 2335305362 M2P_SysMaxVolt_B6_02 "汇流排6单体最大电压  ";
CM_ SG_ 2335305363 M2P_Power_B6_03 "汇流排6实时功率";
CM_ SG_ 2335305363 M2P_SysremEngy_Chg_B6_03 "汇流排6充电剩余能量";
CM_ SG_ 2335305363 M2P_SysremEngy_DisChg_B6_03 "汇流排6放电剩余能量";
CM_ SG_ 2335305363 M2P_SysMaxVolt_B6_03 "汇流排6单体最大电压  ";
CM_ SG_ 2335305364 M2P_Power_B6_04 "汇流排6实时功率";
CM_ SG_ 2335305364 M2P_SysremEngy_Chg_B6_04 "汇流排6充电剩余能量";
CM_ SG_ 2335305364 M2P_SysremEngy_DisChg_B6_04 "汇流排6放电剩余能量";
CM_ SG_ 2335305364 M2P_SysMaxVolt_B6_04 "汇流排6单体最大电压  ";
CM_ SG_ 2335305365 M2P_Power_B6_05 "汇流排6实时功率";
CM_ SG_ 2335305365 M2P_SysremEngy_Chg_B6_05 "汇流排6充电剩余能量";
CM_ SG_ 2335305365 M2P_SysremEngy_DisChg_B6_05 "汇流排6放电剩余能量";
CM_ SG_ 2335305365 M2P_SysMaxVolt_B6_05 "汇流排6单体最大电压  ";
CM_ SG_ 2335305366 M2P_Power_B6_06 "汇流排6实时功率";
CM_ SG_ 2335305366 M2P_SysremEngy_Chg_B6_06 "汇流排6充电剩余能量";
CM_ SG_ 2335305366 M2P_SysremEngy_DisChg_B6_06 "汇流排6放电剩余能量";
CM_ SG_ 2335305366 M2P_SysMaxVolt_B6_06 "汇流排6单体最大电压  ";
CM_ SG_ 2335305367 M2P_Power_B6_07 "汇流排6实时功率";
CM_ SG_ 2335305367 M2P_SysremEngy_Chg_B6_07 "汇流排6充电剩余能量";
CM_ SG_ 2335305367 M2P_SysremEngy_DisChg_B6_07 "汇流排6放电剩余能量";
CM_ SG_ 2335305367 M2P_SysMaxVolt_B6_07 "汇流排6单体最大电压  ";
CM_ SG_ 2335305368 M2P_Power_B6_08 "汇流排6实时功率";
CM_ SG_ 2335305368 M2P_SysremEngy_Chg_B6_08 "汇流排6充电剩余能量";
CM_ SG_ 2335305368 M2P_SysremEngy_DisChg_B6_08 "汇流排6放电剩余能量";
CM_ SG_ 2335305368 M2P_SysMaxVolt_B6_08 "汇流排6单体最大电压  ";
CM_ SG_ 2335305369 M2P_Power_B6_09 "汇流排6实时功率";
CM_ SG_ 2335305369 M2P_SysremEngy_Chg_B6_09 "汇流排6充电剩余能量";
CM_ SG_ 2335305369 M2P_SysremEngy_DisChg_B6_09 "汇流排6放电剩余能量";
CM_ SG_ 2335305369 M2P_SysMaxVolt_B6_09 "汇流排6单体最大电压  ";
CM_ SG_ 2335305370 M2P_Power_B6_10 "汇流排6实时功率";
CM_ SG_ 2335305370 M2P_SysremEngy_Chg_B6_10 "汇流排6充电剩余能量";
CM_ SG_ 2335305370 M2P_SysremEngy_DisChg_B6_10 "汇流排6放电剩余能量";
CM_ SG_ 2335305370 M2P_SysMaxVolt_B6_10 "汇流排6单体最大电压  ";
CM_ SG_ 2335305371 M2P_Power_B6_11 "汇流排6实时功率";
CM_ SG_ 2335305371 M2P_SysremEngy_Chg_B6_11 "汇流排6充电剩余能量";
CM_ SG_ 2335305371 M2P_SysremEngy_DisChg_B6_11 "汇流排6放电剩余能量";
CM_ SG_ 2335305371 M2P_SysMaxVolt_B6_11 "汇流排6单体最大电压  ";
CM_ SG_ 2335305372 M2P_Power_B6_12 "汇流排6实时功率";
CM_ SG_ 2335305372 M2P_SysremEngy_Chg_B6_12 "汇流排6充电剩余能量";
CM_ SG_ 2335305372 M2P_SysremEngy_DisChg_B6_12 "汇流排6放电剩余能量";
CM_ SG_ 2335305372 M2P_SysMaxVolt_B6_12 "汇流排6单体最大电压  ";
CM_ SG_ 2335305373 M2P_Power_B6_13 "汇流排6实时功率";
CM_ SG_ 2335305373 M2P_SysremEngy_Chg_B6_13 "汇流排6充电剩余能量";
CM_ SG_ 2335305373 M2P_SysremEngy_DisChg_B6_13 "汇流排6放电剩余能量";
CM_ SG_ 2335305373 M2P_SysMaxVolt_B6_13 "汇流排6单体最大电压  ";
CM_ SG_ 2335305374 M2P_Power_B6_14 "汇流排6实时功率";
CM_ SG_ 2335305374 M2P_SysremEngy_Chg_B6_14 "汇流排6充电剩余能量";
CM_ SG_ 2335305374 M2P_SysremEngy_DisChg_B6_14 "汇流排6放电剩余能量";
CM_ SG_ 2335305374 M2P_SysMaxVolt_B6_14 "汇流排6单体最大电压  ";
CM_ SG_ 2335305375 M2P_Power_B6_15 "汇流排6实时功率";
CM_ SG_ 2335305375 M2P_SysremEngy_Chg_B6_15 "汇流排6充电剩余能量";
CM_ SG_ 2335305375 M2P_SysremEngy_DisChg_B6_15 "汇流排6放电剩余能量";
CM_ SG_ 2335305375 M2P_SysMaxVolt_B6_15 "汇流排6单体最大电压  ";
CM_ SG_ 2335305376 M2P_Power_B6_16 "汇流排6实时功率";
CM_ SG_ 2335305376 M2P_SysremEngy_Chg_B6_16 "汇流排6充电剩余能量";
CM_ SG_ 2335305376 M2P_SysremEngy_DisChg_B6_16 "汇流排6放电剩余能量";
CM_ SG_ 2335305376 M2P_SysMaxVolt_B6_16 "汇流排6单体最大电压  ";
CM_ SG_ 2335305377 M2P_Power_B6_17 "汇流排6实时功率";
CM_ SG_ 2335305377 M2P_SysremEngy_Chg_B6_17 "汇流排6充电剩余能量";
CM_ SG_ 2335305377 M2P_SysremEngy_DisChg_B6_17 "汇流排6放电剩余能量";
CM_ SG_ 2335305377 M2P_SysMaxVolt_B6_17 "汇流排6单体最大电压  ";
CM_ SG_ 2335305378 M2P_Power_B6_18 "汇流排6实时功率";
CM_ SG_ 2335305378 M2P_SysremEngy_Chg_B6_18 "汇流排6充电剩余能量";
CM_ SG_ 2335305378 M2P_SysremEngy_DisChg_B6_18 "汇流排6放电剩余能量";
CM_ SG_ 2335305378 M2P_SysMaxVolt_B6_18 "汇流排6单体最大电压  ";
CM_ SG_ 2335305379 M2P_Power_B6_19 "汇流排6实时功率";
CM_ SG_ 2335305379 M2P_SysremEngy_Chg_B6_19 "汇流排6充电剩余能量";
CM_ SG_ 2335305379 M2P_SysremEngy_DisChg_B6_19 "汇流排6放电剩余能量";
CM_ SG_ 2335305379 M2P_SysMaxVolt_B6_19 "汇流排6单体最大电压  ";
CM_ SG_ 2335305380 M2P_Power_B6_20 "汇流排6实时功率";
CM_ SG_ 2335305380 M2P_SysremEngy_Chg_B6_20 "汇流排6充电剩余能量";
CM_ SG_ 2335305380 M2P_SysremEngy_DisChg_B6_20 "汇流排6放电剩余能量";
CM_ SG_ 2335305380 M2P_SysMaxVolt_B6_20 "汇流排6单体最大电压  ";
CM_ SG_ 2335305381 M2P_Power_B6_21 "汇流排6实时功率";
CM_ SG_ 2335305381 M2P_SysremEngy_Chg_B6_21 "汇流排6充电剩余能量";
CM_ SG_ 2335305381 M2P_SysremEngy_DisChg_B6_21 "汇流排6放电剩余能量";
CM_ SG_ 2335305381 M2P_SysMaxVolt_B6_21 "汇流排6单体最大电压  ";
VAL_ 2334715557 M2P_BMS_Status_B4 0 "初始化状态" 1 "非满充满放状态" 2 "满充状态" 3 "满放状态" ;
VAL_ 2334715557 M2P_SOC_B4 1023 "Null" ;
VAL_ 2334715557 M2P_SOH_B4 255 "Null" ;
VAL_ 2334715558 M2P_BMS_Status_B4 0 "初始化状态" 1 "非满充满放状态" 2 "满充状态" 3 "满放状态" ;
VAL_ 2334715558 M2P_SOC_B4 1023 "Null" ;
VAL_ 2334715558 M2P_SOH_B4 255 "Null" ;
VAL_ 2334715559 M2P_BMS_Status_B4 0 "初始化状态" 1 "非满充满放状态" 2 "满充状态" 3 "满放状态" ;
VAL_ 2334715559 M2P_SOC_B4 1023 "Null" ;
VAL_ 2334715559 M2P_SOH_B4 255 "Null" ;
VAL_ 2334715560 M2P_BMS_Status_B4 0 "初始化状态" 1 "非满充满放状态" 2 "满充状态" 3 "满放状态" ;
VAL_ 2334715560 M2P_SOC_B4 1023 "Null" ;
VAL_ 2334715560 M2P_SOH_B4 255 "Null" ;
VAL_ 2334715561 M2P_BMS_Status_B4 0 "初始化状态" 1 "非满充满放状态" 2 "满充状态" 3 "满放状态" ;
VAL_ 2334715561 M2P_SOC_B4 1023 "Null" ;
VAL_ 2334715561 M2P_SOH_B4 255 "Null" ;
VAL_ 2334715562 M2P_BMS_Status_B4 0 "初始化状态" 1 "非满充满放状态" 2 "满充状态" 3 "满放状态" ;
VAL_ 2334715562 M2P_SOC_B4 1023 "Null" ;
VAL_ 2334715562 M2P_SOH_B4 255 "Null" ;
VAL_ 2334715563 M2P_BMS_Status_B4 0 "初始化状态" 1 "非满充满放状态" 2 "满充状态" 3 "满放状态" ;
VAL_ 2334715563 M2P_SOC_B4 1023 "Null" ;
VAL_ 2334715563 M2P_SOH_B4 255 "Null" ;
VAL_ 2334715564 M2P_BMS_Status_B4 0 "初始化状态" 1 "非满充满放状态" 2 "满充状态" 3 "满放状态" ;
VAL_ 2334715564 M2P_SOC_B4 1023 "Null" ;
VAL_ 2334715564 M2P_SOH_B4 255 "Null" ;
VAL_ 2334715565 M2P_BMS_Status_B4 0 "初始化状态" 1 "非满充满放状态" 2 "满充状态" 3 "满放状态" ;
VAL_ 2334715565 M2P_SOC_B4 1023 "Null" ;
VAL_ 2334715565 M2P_SOH_B4 255 "Null" ;
VAL_ 2334715566 M2P_BMS_Status_B4 0 "初始化状态" 1 "非满充满放状态" 2 "满充状态" 3 "满放状态" ;
VAL_ 2334715566 M2P_SOC_B4 1023 "Null" ;
VAL_ 2334715566 M2P_SOH_B4 255 "Null" ;
VAL_ 2334715567 M2P_BMS_Status_B4 0 "初始化状态" 1 "非满充满放状态" 2 "满充状态" 3 "满放状态" ;
VAL_ 2334715567 M2P_SOC_B4 1023 "Null" ;
VAL_ 2334715567 M2P_SOH_B4 255 "Null" ;
VAL_ 2334781073 M2P_SOE_Charge_B4 1023 "Null" ;
VAL_ 2334781073 M2P_SOE_Discharge_B4 1023 "Null" ;
VAL_ 2334781074 M2P_SOE_Charge_B4 1023 "Null" ;
VAL_ 2334781074 M2P_SOE_Discharge_B4 1023 "Null" ;
VAL_ 2334781075 M2P_SOE_Charge_B4 1023 "Null" ;
VAL_ 2334781075 M2P_SOE_Discharge_B4 1023 "Null" ;
VAL_ 2334781076 M2P_SOE_Charge_B4 1023 "Null" ;
VAL_ 2334781076 M2P_SOE_Discharge_B4 1023 "Null" ;
VAL_ 2334781077 M2P_SOE_Charge_B4 1023 "Null" ;
VAL_ 2334781077 M2P_SOE_Discharge_B4 1023 "Null" ;
VAL_ 2334781078 M2P_SOE_Charge_B4 1023 "Null" ;
VAL_ 2334781078 M2P_SOE_Discharge_B4 1023 "Null" ;
VAL_ 2334781079 M2P_SOE_Charge_B4 1023 "Null" ;
VAL_ 2334781079 M2P_SOE_Discharge_B4 1023 "Null" ;
VAL_ 2334781080 M2P_SOE_Charge_B4 1023 "Null" ;
VAL_ 2334781080 M2P_SOE_Discharge_B4 1023 "Null" ;
VAL_ 2334781081 M2P_SOE_Charge_B4 1023 "Null" ;
VAL_ 2334781081 M2P_SOE_Discharge_B4 1023 "Null" ;
VAL_ 2334781082 M2P_SOE_Charge_B4 1023 "Null" ;
VAL_ 2334781082 M2P_SOE_Discharge_B4 1023 "Null" ;
VAL_ 2334781083 M2P_SOE_Charge_B4 1023 "Null" ;
VAL_ 2334781083 M2P_SOE_Discharge_B4 1023 "Null" ;
VAL_ 2334781084 M2P_SOE_Charge_B4 1023 "Null" ;
VAL_ 2334781084 M2P_SOE_Discharge_B4 1023 "Null" ;
VAL_ 2334781085 M2P_SOE_Charge_B4 1023 "Null" ;
VAL_ 2334781085 M2P_SOE_Discharge_B4 1023 "Null" ;
VAL_ 2334781086 M2P_SOE_Charge_B4 1023 "Null" ;
VAL_ 2334781086 M2P_SOE_Discharge_B4 1023 "Null" ;
VAL_ 2334781087 M2P_SOE_Charge_B4 1023 "Null" ;
VAL_ 2334781087 M2P_SOE_Discharge_B4 1023 "Null" ;
VAL_ 2334781088 M2P_SOE_Charge_B4 1023 "Null" ;
VAL_ 2334781088 M2P_SOE_Discharge_B4 1023 "Null" ;
VAL_ 2334781089 M2P_SOE_Charge_B4 1023 "Null" ;
VAL_ 2334781089 M2P_SOE_Discharge_B4 1023 "Null" ;
VAL_ 2334781090 M2P_SOE_Charge_B4 1023 "Null" ;
VAL_ 2334781090 M2P_SOE_Discharge_B4 1023 "Null" ;
VAL_ 2334781091 M2P_SOE_Charge_B4 1023 "Null" ;
VAL_ 2334781091 M2P_SOE_Discharge_B4 1023 "Null" ;
VAL_ 2334781092 M2P_SOE_Charge_B4 1023 "Null" ;
VAL_ 2334781092 M2P_SOE_Discharge_B4 1023 "Null" ;
VAL_ 2334781093 M2P_SOE_Charge_B4 1023 "Null" ;
VAL_ 2334781093 M2P_SOE_Discharge_B4 1023 "Null" ;
VAL_ 2334781094 M2P_SOE_Charge_B4 1023 "Null" ;
VAL_ 2334781094 M2P_SOE_Discharge_B4 1023 "Null" ;
VAL_ 2334781095 M2P_SOE_Charge_B4 1023 "Null" ;
VAL_ 2334781095 M2P_SOE_Discharge_B4 1023 "Null" ;
VAL_ 2334781096 M2P_SOE_Charge_B4 1023 "Null" ;
VAL_ 2334781096 M2P_SOE_Discharge_B4 1023 "Null" ;
VAL_ 2334781097 M2P_SOE_Charge_B4 1023 "Null" ;
VAL_ 2334781097 M2P_SOE_Discharge_B4 1023 "Null" ;
VAL_ 2334781098 M2P_SOE_Charge_B4 1023 "Null" ;
VAL_ 2334781098 M2P_SOE_Discharge_B4 1023 "Null" ;
VAL_ 2334781099 M2P_SOE_Charge_B4 1023 "Null" ;
VAL_ 2334781099 M2P_SOE_Discharge_B4 1023 "Null" ;
VAL_ 2334781100 M2P_SOE_Charge_B4 1023 "Null" ;
VAL_ 2334781100 M2P_SOE_Discharge_B4 1023 "Null" ;
VAL_ 2334781101 M2P_SOE_Charge_B4 1023 "Null" ;
VAL_ 2334781101 M2P_SOE_Discharge_B4 1023 "Null" ;
VAL_ 2334781102 M2P_SOE_Charge_B4 1023 "Null" ;
VAL_ 2334781102 M2P_SOE_Discharge_B4 1023 "Null" ;
VAL_ 2334781103 M2P_SOE_Charge_B4 1023 "Null" ;
VAL_ 2334781103 M2P_SOE_Discharge_B4 1023 "Null" ;
VAL_ 2334846609 M2P_Measure_Vol_B5_01 65535 "Invalid" ;
VAL_ 2334846609 M2P_Current_B5_01 65535 "Invalid" ;
VAL_ 2334846609 M2P_PermitMaxCharge_I_B5_01 65535 "Invalid" ;
VAL_ 2334846609 M2P_PermitMaxDisCharge_I_B5_01 65535 "Invalid" ;
VAL_ 2334846610 M2P_Measure_Vol_B5_02 65535 "Invalid" ;
VAL_ 2334846610 M2P_Current_B5_02 65535 "Invalid" ;
VAL_ 2334846610 M2P_PermitMaxCharge_I_B5_02 65535 "Invalid" ;
VAL_ 2334846610 M2P_PermitMaxDisCharge_I_B5_02 65535 "Invalid" ;
VAL_ 2334846611 M2P_Measure_Vol_B5_03 65535 "Invalid" ;
VAL_ 2334846611 M2P_Current_B5_03 65535 "Invalid" ;
VAL_ 2334846611 M2P_PermitMaxCharge_I_B5_03 65535 "Invalid" ;
VAL_ 2334846611 M2P_PermitMaxDisCharge_I_B5_03 65535 "Invalid" ;
VAL_ 2334846612 M2P_Measure_Vol_B5_04 65535 "Invalid" ;
VAL_ 2334846612 M2P_Current_B5_04 65535 "Invalid" ;
VAL_ 2334846612 M2P_PermitMaxCharge_I_B5_04 65535 "Invalid" ;
VAL_ 2334846612 M2P_PermitMaxDisCharge_I_B5_04 65535 "Invalid" ;
VAL_ 2334846613 M2P_Measure_Vol_B5_05 65535 "Invalid" ;
VAL_ 2334846613 M2P_Current_B5_05 65535 "Invalid" ;
VAL_ 2334846613 M2P_PermitMaxCharge_I_B5_05 65535 "Invalid" ;
VAL_ 2334846613 M2P_PermitMaxDisCharge_I_B5_05 65535 "Invalid" ;
VAL_ 2334846614 M2P_Measure_Vol_B5_06 65535 "Invalid" ;
VAL_ 2334846614 M2P_Current_B5_06 65535 "Invalid" ;
VAL_ 2334846614 M2P_PermitMaxCharge_I_B5_06 65535 "Invalid" ;
VAL_ 2334846614 M2P_PermitMaxDisCharge_I_B5_06 65535 "Invalid" ;
VAL_ 2334846615 M2P_Measure_Vol_B5_07 65535 "Invalid" ;
VAL_ 2334846615 M2P_Current_B5_07 65535 "Invalid" ;
VAL_ 2334846615 M2P_PermitMaxCharge_I_B5_07 65535 "Invalid" ;
VAL_ 2334846615 M2P_PermitMaxDisCharge_I_B5_07 65535 "Invalid" ;
VAL_ 2334846616 M2P_Measure_Vol_B5_08 65535 "Invalid" ;
VAL_ 2334846616 M2P_Current_B5_08 65535 "Invalid" ;
VAL_ 2334846616 M2P_PermitMaxCharge_I_B5_08 65535 "Invalid" ;
VAL_ 2334846616 M2P_PermitMaxDisCharge_I_B5_08 65535 "Invalid" ;
VAL_ 2334846617 M2P_Measure_Vol_B5_09 65535 "Invalid" ;
VAL_ 2334846617 M2P_Current_B5_09 65535 "Invalid" ;
VAL_ 2334846617 M2P_PermitMaxCharge_I_B5_09 65535 "Invalid" ;
VAL_ 2334846617 M2P_PermitMaxDisCharge_I_B5_09 65535 "Invalid" ;
VAL_ 2334846618 M2P_Measure_Vol_B5_10 65535 "Invalid" ;
VAL_ 2334846618 M2P_Current_B5_10 65535 "Invalid" ;
VAL_ 2334846618 M2P_PermitMaxCharge_I_B5_10 65535 "Invalid" ;
VAL_ 2334846618 M2P_PermitMaxDisCharge_I_B5_10 65535 "Invalid" ;
VAL_ 2334846619 M2P_Measure_Vol_B5_11 65535 "Invalid" ;
VAL_ 2334846619 M2P_Current_B5_11 65535 "Invalid" ;
VAL_ 2334846619 M2P_PermitMaxCharge_I_B5_11 65535 "Invalid" ;
VAL_ 2334846619 M2P_PermitMaxDisCharge_I_B5_11 65535 "Invalid" ;
VAL_ 2334846620 M2P_Measure_Vol_B5_12 65535 "Invalid" ;
VAL_ 2334846620 M2P_Current_B5_12 65535 "Invalid" ;
VAL_ 2334846620 M2P_PermitMaxCharge_I_B5_12 65535 "Invalid" ;
VAL_ 2334846620 M2P_PermitMaxDisCharge_I_B5_12 65535 "Invalid" ;
VAL_ 2334846621 M2P_Measure_Vol_B5_13 65535 "Invalid" ;
VAL_ 2334846621 M2P_Current_B5_13 65535 "Invalid" ;
VAL_ 2334846621 M2P_PermitMaxCharge_I_B5_13 65535 "Invalid" ;
VAL_ 2334846621 M2P_PermitMaxDisCharge_I_B5_13 65535 "Invalid" ;
VAL_ 2334846622 M2P_Measure_Vol_B5_14 65535 "Invalid" ;
VAL_ 2334846622 M2P_Current_B5_14 65535 "Invalid" ;
VAL_ 2334846622 M2P_PermitMaxCharge_I_B5_14 65535 "Invalid" ;
VAL_ 2334846622 M2P_PermitMaxDisCharge_I_B5_14 65535 "Invalid" ;
VAL_ 2334846623 M2P_Measure_Vol_B5_15 65535 "Invalid" ;
VAL_ 2334846623 M2P_Current_B5_15 65535 "Invalid" ;
VAL_ 2334846623 M2P_PermitMaxCharge_I_B5_15 65535 "Invalid" ;
VAL_ 2334846623 M2P_PermitMaxDisCharge_I_B5_15 65535 "Invalid" ;
VAL_ 2334846624 M2P_Measure_Vol_B5_16 65535 "Invalid" ;
VAL_ 2334846624 M2P_Current_B5_16 65535 "Invalid" ;
VAL_ 2334846624 M2P_PermitMaxCharge_I_B5_16 65535 "Invalid" ;
VAL_ 2334846624 M2P_PermitMaxDisCharge_I_B5_16 65535 "Invalid" ;
VAL_ 2334846625 M2P_Measure_Vol_B5_17 65535 "Invalid" ;
VAL_ 2334846625 M2P_Current_B5_17 65535 "Invalid" ;
VAL_ 2334846625 M2P_PermitMaxCharge_I_B5_17 65535 "Invalid" ;
VAL_ 2334846625 M2P_PermitMaxDisCharge_I_B5_17 65535 "Invalid" ;
VAL_ 2334846626 M2P_Measure_Vol_B5_18 65535 "Invalid" ;
VAL_ 2334846626 M2P_Current_B5_18 65535 "Invalid" ;
VAL_ 2334846626 M2P_PermitMaxCharge_I_B5_18 65535 "Invalid" ;
VAL_ 2334846626 M2P_PermitMaxDisCharge_I_B5_18 65535 "Invalid" ;
VAL_ 2334846627 M2P_Measure_Vol_B5_19 65535 "Invalid" ;
VAL_ 2334846627 M2P_Current_B5_19 65535 "Invalid" ;
VAL_ 2334846627 M2P_PermitMaxCharge_I_B5_19 65535 "Invalid" ;
VAL_ 2334846627 M2P_PermitMaxDisCharge_I_B5_19 65535 "Invalid" ;
VAL_ 2334846628 M2P_Measure_Vol_B5_20 65535 "Invalid" ;
VAL_ 2334846628 M2P_Current_B5_20 65535 "Invalid" ;
VAL_ 2334846628 M2P_PermitMaxCharge_I_B5_20 65535 "Invalid" ;
VAL_ 2334846628 M2P_PermitMaxDisCharge_I_B5_20 65535 "Invalid" ;
VAL_ 2334846629 M2P_Measure_Vol_B5_21 65535 "Invalid" ;
VAL_ 2334846629 M2P_Current_B5_21 65535 "Invalid" ;
VAL_ 2334846629 M2P_PermitMaxCharge_I_B5_21 65535 "Invalid" ;
VAL_ 2334846629 M2P_PermitMaxDisCharge_I_B5_21 65535 "Invalid" ;
VAL_ 2334846630 M2P_Measure_Vol_B5_22 65535 "Invalid" ;
VAL_ 2334846630 M2P_Current_B5_22 65535 "Invalid" ;
VAL_ 2334846630 M2P_PermitMaxCharge_I_B5_22 65535 "Invalid" ;
VAL_ 2334846630 M2P_PermitMaxDisCharge_I_B5_22 65535 "Invalid" ;
VAL_ 2334846631 M2P_Measure_Vol_B5_23 65535 "Invalid" ;
VAL_ 2334846631 M2P_Current_B5_23 65535 "Invalid" ;
VAL_ 2334846631 M2P_PermitMaxCharge_I_B5_23 65535 "Invalid" ;
VAL_ 2334846631 M2P_PermitMaxDisCharge_I_B5_23 65535 "Invalid" ;
VAL_ 2334846632 M2P_Measure_Vol_B5_24 65535 "Invalid" ;
VAL_ 2334846632 M2P_Current_B5_24 65535 "Invalid" ;
VAL_ 2334846632 M2P_PermitMaxCharge_I_B5_24 65535 "Invalid" ;
VAL_ 2334846632 M2P_PermitMaxDisCharge_I_B5_24 65535 "Invalid" ;
VAL_ 2334846633 M2P_Measure_Vol_B5_25 65535 "Invalid" ;
VAL_ 2334846633 M2P_Current_B5_25 65535 "Invalid" ;
VAL_ 2334846633 M2P_PermitMaxCharge_I_B5_25 65535 "Invalid" ;
VAL_ 2334846633 M2P_PermitMaxDisCharge_I_B5_25 65535 "Invalid" ;
VAL_ 2334846634 M2P_Measure_Vol_B5_26 65535 "Invalid" ;
VAL_ 2334846634 M2P_Current_B5_26 65535 "Invalid" ;
VAL_ 2334846634 M2P_PermitMaxCharge_I_B5_26 65535 "Invalid" ;
VAL_ 2334846634 M2P_PermitMaxDisCharge_I_B5_26 65535 "Invalid" ;
VAL_ 2334846635 M2P_Measure_Vol_B5_27 65535 "Invalid" ;
VAL_ 2334846635 M2P_Current_B5_27 65535 "Invalid" ;
VAL_ 2334846635 M2P_PermitMaxCharge_I_B5_27 65535 "Invalid" ;
VAL_ 2334846635 M2P_PermitMaxDisCharge_I_B5_27 65535 "Invalid" ;
VAL_ 2334846636 M2P_Measure_Vol_B5_28 65535 "Invalid" ;
VAL_ 2334846636 M2P_Current_B5_28 65535 "Invalid" ;
VAL_ 2334846636 M2P_PermitMaxCharge_I_B5_28 65535 "Invalid" ;
VAL_ 2334846636 M2P_PermitMaxDisCharge_I_B5_28 65535 "Invalid" ;
VAL_ 2334846637 M2P_Measure_Vol_B5_29 65535 "Invalid" ;
VAL_ 2334846637 M2P_Current_B5_29 65535 "Invalid" ;
VAL_ 2334846637 M2P_PermitMaxCharge_I_B5_29 65535 "Invalid" ;
VAL_ 2334846637 M2P_PermitMaxDisCharge_I_B5_29 65535 "Invalid" ;
VAL_ 2334846638 M2P_Measure_Vol_B5_30 65535 "Invalid" ;
VAL_ 2334846638 M2P_Current_B5_30 65535 "Invalid" ;
VAL_ 2334846638 M2P_PermitMaxCharge_I_B5_30 65535 "Invalid" ;
VAL_ 2334846638 M2P_PermitMaxDisCharge_I_B5_30 65535 "Invalid" ;
VAL_ 2334846639 M2P_Measure_Vol_B5_31 65535 "Invalid" ;
VAL_ 2334846639 M2P_Current_B5_31 65535 "Invalid" ;
VAL_ 2334846639 M2P_PermitMaxCharge_I_B5_31 65535 "Invalid" ;
VAL_ 2334846639 M2P_PermitMaxDisCharge_I_B5_31 65535 "Invalid" ;
VAL_ 2334977681 M2P_SysremEngy_Chg_B5_01 65535 "Invalid" ;
VAL_ 2334977681 M2P_SysremEngy_DisChg_B5_01 65535 "Invalid" ;
VAL_ 2334977682 M2P_SysremEngy_Chg_B5_02 65535 "Invalid" ;
VAL_ 2334977682 M2P_SysremEngy_DisChg_B5_02 65535 "Invalid" ;
VAL_ 2334977683 M2P_SysremEngy_Chg_B5_03 65535 "Invalid" ;
VAL_ 2334977683 M2P_SysremEngy_DisChg_B5_03 65535 "Invalid" ;
VAL_ 2334977684 M2P_SysremEngy_Chg_B5_04 65535 "Invalid" ;
VAL_ 2334977684 M2P_SysremEngy_DisChg_B5_04 65535 "Invalid" ;
VAL_ 2334977685 M2P_SysremEngy_Chg_B5_05 65535 "Invalid" ;
VAL_ 2334977685 M2P_SysremEngy_DisChg_B5_05 65535 "Invalid" ;
VAL_ 2334977686 M2P_SysremEngy_Chg_B5_06 65535 "Invalid" ;
VAL_ 2334977686 M2P_SysremEngy_DisChg_B5_06 65535 "Invalid" ;
VAL_ 2334977687 M2P_SysremEngy_Chg_B5_07 65535 "Invalid" ;
VAL_ 2334977687 M2P_SysremEngy_DisChg_B5_07 65535 "Invalid" ;
VAL_ 2334977688 M2P_SysremEngy_Chg_B5_08 65535 "Invalid" ;
VAL_ 2334977688 M2P_SysremEngy_DisChg_B5_08 65535 "Invalid" ;
VAL_ 2334977689 M2P_SysremEngy_Chg_B5_09 65535 "Invalid" ;
VAL_ 2334977689 M2P_SysremEngy_DisChg_B5_09 65535 "Invalid" ;
VAL_ 2334977690 M2P_SysremEngy_Chg_B5_10 65535 "Invalid" ;
VAL_ 2334977690 M2P_SysremEngy_DisChg_B5_10 65535 "Invalid" ;
VAL_ 2334977691 M2P_SysremEngy_Chg_B5_11 65535 "Invalid" ;
VAL_ 2334977691 M2P_SysremEngy_DisChg_B5_11 65535 "Invalid" ;
VAL_ 2334977692 M2P_SysremEngy_Chg_B5_12 65535 "Invalid" ;
VAL_ 2334977692 M2P_SysremEngy_DisChg_B5_12 65535 "Invalid" ;
VAL_ 2334977693 M2P_SysremEngy_Chg_B5_13 65535 "Invalid" ;
VAL_ 2334977693 M2P_SysremEngy_DisChg_B5_13 65535 "Invalid" ;
VAL_ 2334977694 M2P_SysremEngy_Chg_B5_14 65535 "Invalid" ;
VAL_ 2334977694 M2P_SysremEngy_DisChg_B5_14 65535 "Invalid" ;
VAL_ 2334977695 M2P_SysremEngy_Chg_B5_15 65535 "Invalid" ;
VAL_ 2334977695 M2P_SysremEngy_DisChg_B5_15 65535 "Invalid" ;
VAL_ 2334977696 M2P_SysremEngy_Chg_B5_16 65535 "Invalid" ;
VAL_ 2334977696 M2P_SysremEngy_DisChg_B5_16 65535 "Invalid" ;
VAL_ 2334977697 M2P_SysremEngy_Chg_B5_17 65535 "Invalid" ;
VAL_ 2334977697 M2P_SysremEngy_DisChg_B5_17 65535 "Invalid" ;
VAL_ 2334977698 M2P_SysremEngy_Chg_B5_18 65535 "Invalid" ;
VAL_ 2334977698 M2P_SysremEngy_DisChg_B5_18 65535 "Invalid" ;
VAL_ 2334977699 M2P_SysremEngy_Chg_B5_19 65535 "Invalid" ;
VAL_ 2334977699 M2P_SysremEngy_DisChg_B5_19 65535 "Invalid" ;
VAL_ 2334977700 M2P_SysremEngy_Chg_B5_20 65535 "Invalid" ;
VAL_ 2334977700 M2P_SysremEngy_DisChg_B5_20 65535 "Invalid" ;
VAL_ 2334977701 M2P_SysremEngy_Chg_B5_21 65535 "Invalid" ;
VAL_ 2334977701 M2P_SysremEngy_DisChg_B5_21 65535 "Invalid" ;
VAL_ 2334977702 M2P_SysremEngy_Chg_B5_22 65535 "Invalid" ;
VAL_ 2334977702 M2P_SysremEngy_DisChg_B5_22 65535 "Invalid" ;
VAL_ 2334977703 M2P_SysremEngy_Chg_B5_23 65535 "Invalid" ;
VAL_ 2334977703 M2P_SysremEngy_DisChg_B5_23 65535 "Invalid" ;
VAL_ 2334977704 M2P_SysremEngy_Chg_B5_24 65535 "Invalid" ;
VAL_ 2334977704 M2P_SysremEngy_DisChg_B5_24 65535 "Invalid" ;
VAL_ 2334977705 M2P_SysremEngy_Chg_B5_25 65535 "Invalid" ;
VAL_ 2334977705 M2P_SysremEngy_DisChg_B5_25 65535 "Invalid" ;
VAL_ 2334977706 M2P_SysremEngy_Chg_B5_26 65535 "Invalid" ;
VAL_ 2334977706 M2P_SysremEngy_DisChg_B5_26 65535 "Invalid" ;
VAL_ 2334977707 M2P_SysremEngy_Chg_B5_27 65535 "Invalid" ;
VAL_ 2334977707 M2P_SysremEngy_DisChg_B5_27 65535 "Invalid" ;
VAL_ 2334977708 M2P_SysremEngy_Chg_B5_28 65535 "Invalid" ;
VAL_ 2334977708 M2P_SysremEngy_DisChg_B5_28 65535 "Invalid" ;
VAL_ 2334977709 M2P_SysremEngy_Chg_B5_29 65535 "Invalid" ;
VAL_ 2334977709 M2P_SysremEngy_DisChg_B5_29 65535 "Invalid" ;
VAL_ 2334977710 M2P_SysremEngy_Chg_B5_30 65535 "Invalid" ;
VAL_ 2334977710 M2P_SysremEngy_DisChg_B5_30 65535 "Invalid" ;
VAL_ 2334977711 M2P_SysremEngy_Chg_B5_31 65535 "Invalid" ;
VAL_ 2334977711 M2P_SysremEngy_DisChg_B5_31 65535 "Invalid" ;
VAL_ 2335043217 M2P_BMS_Status_B5 0 "初始化状态" 1 "非满充满放状态" 2 "满充状态" 3 "满放状态" ;
VAL_ 2335043217 M2P_SOC_B5 1023 "Null" ;
VAL_ 2335043217 M2P_SOH_B5 255 "Null" ;
VAL_ 2335043218 M2P_BMS_Status_B5 0 "初始化状态" 1 "非满充满放状态" 2 "满充状态" 3 "满放状态" ;
VAL_ 2335043218 M2P_SOC_B5 1023 "Null" ;
VAL_ 2335043218 M2P_SOH_B5 255 "Null" ;
VAL_ 2335043219 M2P_BMS_Status_B5 0 "初始化状态" 1 "非满充满放状态" 2 "满充状态" 3 "满放状态" ;
VAL_ 2335043219 M2P_SOC_B5 1023 "Null" ;
VAL_ 2335043219 M2P_SOH_B5 255 "Null" ;
VAL_ 2335043220 M2P_BMS_Status_B5 0 "初始化状态" 1 "非满充满放状态" 2 "满充状态" 3 "满放状态" ;
VAL_ 2335043220 M2P_SOC_B5 1023 "Null" ;
VAL_ 2335043220 M2P_SOH_B5 255 "Null" ;
VAL_ 2335043221 M2P_BMS_Status_B5 0 "初始化状态" 1 "非满充满放状态" 2 "满充状态" 3 "满放状态" ;
VAL_ 2335043221 M2P_SOC_B5 1023 "Null" ;
VAL_ 2335043221 M2P_SOH_B5 255 "Null" ;
VAL_ 2335043222 M2P_BMS_Status_B5 0 "初始化状态" 1 "非满充满放状态" 2 "满充状态" 3 "满放状态" ;
VAL_ 2335043222 M2P_SOC_B5 1023 "Null" ;
VAL_ 2335043222 M2P_SOH_B5 255 "Null" ;
VAL_ 2335043223 M2P_BMS_Status_B5 0 "初始化状态" 1 "非满充满放状态" 2 "满充状态" 3 "满放状态" ;
VAL_ 2335043223 M2P_SOC_B5 1023 "Null" ;
VAL_ 2335043223 M2P_SOH_B5 255 "Null" ;
VAL_ 2335043224 M2P_BMS_Status_B5 0 "初始化状态" 1 "非满充满放状态" 2 "满充状态" 3 "满放状态" ;
VAL_ 2335043224 M2P_SOC_B5 1023 "Null" ;
VAL_ 2335043224 M2P_SOH_B5 255 "Null" ;
VAL_ 2335043225 M2P_BMS_Status_B5 0 "初始化状态" 1 "非满充满放状态" 2 "满充状态" 3 "满放状态" ;
VAL_ 2335043225 M2P_SOC_B5 1023 "Null" ;
VAL_ 2335043225 M2P_SOH_B5 255 "Null" ;
VAL_ 2335043226 M2P_BMS_Status_B5 0 "初始化状态" 1 "非满充满放状态" 2 "满充状态" 3 "满放状态" ;
VAL_ 2335043226 M2P_SOC_B5 1023 "Null" ;
VAL_ 2335043226 M2P_SOH_B5 255 "Null" ;
VAL_ 2335043227 M2P_BMS_Status_B5 0 "初始化状态" 1 "非满充满放状态" 2 "满充状态" 3 "满放状态" ;
VAL_ 2335043227 M2P_SOC_B5 1023 "Null" ;
VAL_ 2335043227 M2P_SOH_B5 255 "Null" ;
VAL_ 2335043228 M2P_BMS_Status_B5 0 "初始化状态" 1 "非满充满放状态" 2 "满充状态" 3 "满放状态" ;
VAL_ 2335043228 M2P_SOC_B5 1023 "Null" ;
VAL_ 2335043228 M2P_SOH_B5 255 "Null" ;
VAL_ 2335043229 M2P_BMS_Status_B5 0 "初始化状态" 1 "非满充满放状态" 2 "满充状态" 3 "满放状态" ;
VAL_ 2335043229 M2P_SOC_B5 1023 "Null" ;
VAL_ 2335043229 M2P_SOH_B5 255 "Null" ;
VAL_ 2335043230 M2P_BMS_Status_B5 0 "初始化状态" 1 "非满充满放状态" 2 "满充状态" 3 "满放状态" ;
VAL_ 2335043230 M2P_SOC_B5 1023 "Null" ;
VAL_ 2335043230 M2P_SOH_B5 255 "Null" ;
VAL_ 2335043231 M2P_BMS_Status_B5 0 "初始化状态" 1 "非满充满放状态" 2 "满充状态" 3 "满放状态" ;
VAL_ 2335043231 M2P_SOC_B5 1023 "Null" ;
VAL_ 2335043231 M2P_SOH_B5 255 "Null" ;
VAL_ 2335043232 M2P_BMS_Status_B5 0 "初始化状态" 1 "非满充满放状态" 2 "满充状态" 3 "满放状态" ;
VAL_ 2335043232 M2P_SOC_B5 1023 "Null" ;
VAL_ 2335043232 M2P_SOH_B5 255 "Null" ;
VAL_ 2335043233 M2P_BMS_Status_B5 0 "初始化状态" 1 "非满充满放状态" 2 "满充状态" 3 "满放状态" ;
VAL_ 2335043233 M2P_SOC_B5 1023 "Null" ;
VAL_ 2335043233 M2P_SOH_B5 255 "Null" ;
VAL_ 2335043234 M2P_BMS_Status_B5 0 "初始化状态" 1 "非满充满放状态" 2 "满充状态" 3 "满放状态" ;
VAL_ 2335043234 M2P_SOC_B5 1023 "Null" ;
VAL_ 2335043234 M2P_SOH_B5 255 "Null" ;
VAL_ 2335043235 M2P_BMS_Status_B5 0 "初始化状态" 1 "非满充满放状态" 2 "满充状态" 3 "满放状态" ;
VAL_ 2335043235 M2P_SOC_B5 1023 "Null" ;
VAL_ 2335043235 M2P_SOH_B5 255 "Null" ;
VAL_ 2335043236 M2P_BMS_Status_B5 0 "初始化状态" 1 "非满充满放状态" 2 "满充状态" 3 "满放状态" ;
VAL_ 2335043236 M2P_SOC_B5 1023 "Null" ;
VAL_ 2335043236 M2P_SOH_B5 255 "Null" ;
VAL_ 2335043237 M2P_BMS_Status_B5 0 "初始化状态" 1 "非满充满放状态" 2 "满充状态" 3 "满放状态" ;
VAL_ 2335043237 M2P_SOC_B5 1023 "Null" ;
VAL_ 2335043237 M2P_SOH_B5 255 "Null" ;
VAL_ 2335043238 M2P_BMS_Status_B5 0 "初始化状态" 1 "非满充满放状态" 2 "满充状态" 3 "满放状态" ;
VAL_ 2335043238 M2P_SOC_B5 1023 "Null" ;
VAL_ 2335043238 M2P_SOH_B5 255 "Null" ;
VAL_ 2335043239 M2P_BMS_Status_B5 0 "初始化状态" 1 "非满充满放状态" 2 "满充状态" 3 "满放状态" ;
VAL_ 2335043239 M2P_SOC_B5 1023 "Null" ;
VAL_ 2335043239 M2P_SOH_B5 255 "Null" ;
VAL_ 2335043240 M2P_BMS_Status_B5 0 "初始化状态" 1 "非满充满放状态" 2 "满充状态" 3 "满放状态" ;
VAL_ 2335043240 M2P_SOC_B5 1023 "Null" ;
VAL_ 2335043240 M2P_SOH_B5 255 "Null" ;
VAL_ 2335043241 M2P_BMS_Status_B5 0 "初始化状态" 1 "非满充满放状态" 2 "满充状态" 3 "满放状态" ;
VAL_ 2335043241 M2P_SOC_B5 1023 "Null" ;
VAL_ 2335043241 M2P_SOH_B5 255 "Null" ;
VAL_ 2335043242 M2P_BMS_Status_B5 0 "初始化状态" 1 "非满充满放状态" 2 "满充状态" 3 "满放状态" ;
VAL_ 2335043242 M2P_SOC_B5 1023 "Null" ;
VAL_ 2335043242 M2P_SOH_B5 255 "Null" ;
VAL_ 2335043243 M2P_BMS_Status_B5 0 "初始化状态" 1 "非满充满放状态" 2 "满充状态" 3 "满放状态" ;
VAL_ 2335043243 M2P_SOC_B5 1023 "Null" ;
VAL_ 2335043243 M2P_SOH_B5 255 "Null" ;
VAL_ 2335043244 M2P_BMS_Status_B5 0 "初始化状态" 1 "非满充满放状态" 2 "满充状态" 3 "满放状态" ;
VAL_ 2335043244 M2P_SOC_B5 1023 "Null" ;
VAL_ 2335043244 M2P_SOH_B5 255 "Null" ;
VAL_ 2335043245 M2P_BMS_Status_B5 0 "初始化状态" 1 "非满充满放状态" 2 "满充状态" 3 "满放状态" ;
VAL_ 2335043245 M2P_SOC_B5 1023 "Null" ;
VAL_ 2335043245 M2P_SOH_B5 255 "Null" ;
VAL_ 2335043246 M2P_BMS_Status_B5 0 "初始化状态" 1 "非满充满放状态" 2 "满充状态" 3 "满放状态" ;
VAL_ 2335043246 M2P_SOC_B5 1023 "Null" ;
VAL_ 2335043246 M2P_SOH_B5 255 "Null" ;
VAL_ 2335043247 M2P_BMS_Status_B5 0 "初始化状态" 1 "非满充满放状态" 2 "满充状态" 3 "满放状态" ;
VAL_ 2335043247 M2P_SOC_B5 1023 "Null" ;
VAL_ 2335043247 M2P_SOH_B5 255 "Null" ;
VAL_ 2335108753 M2P_SOE_Charge_B5 1023 "Null" ;
VAL_ 2335108753 M2P_SOE_Discharge_B5 1023 "Null" ;
VAL_ 2335108754 M2P_SOE_Charge_B5 1023 "Null" ;
VAL_ 2335108754 M2P_SOE_Discharge_B5 1023 "Null" ;
VAL_ 2335108755 M2P_SOE_Charge_B5 1023 "Null" ;
VAL_ 2335108755 M2P_SOE_Discharge_B5 1023 "Null" ;
VAL_ 2335108756 M2P_SOE_Charge_B5 1023 "Null" ;
VAL_ 2335108756 M2P_SOE_Discharge_B5 1023 "Null" ;
VAL_ 2335108757 M2P_SOE_Charge_B5 1023 "Null" ;
VAL_ 2335108757 M2P_SOE_Discharge_B5 1023 "Null" ;
VAL_ 2335108758 M2P_SOE_Charge_B5 1023 "Null" ;
VAL_ 2335108758 M2P_SOE_Discharge_B5 1023 "Null" ;
VAL_ 2335108759 M2P_SOE_Charge_B5 1023 "Null" ;
VAL_ 2335108759 M2P_SOE_Discharge_B5 1023 "Null" ;
VAL_ 2335108760 M2P_SOE_Charge_B5 1023 "Null" ;
VAL_ 2335108760 M2P_SOE_Discharge_B5 1023 "Null" ;
VAL_ 2335108761 M2P_SOE_Charge_B5 1023 "Null" ;
VAL_ 2335108761 M2P_SOE_Discharge_B5 1023 "Null" ;
VAL_ 2335108762 M2P_SOE_Charge_B5 1023 "Null" ;
VAL_ 2335108762 M2P_SOE_Discharge_B5 1023 "Null" ;
VAL_ 2335108763 M2P_SOE_Charge_B5 1023 "Null" ;
VAL_ 2335108763 M2P_SOE_Discharge_B5 1023 "Null" ;
VAL_ 2335108764 M2P_SOE_Charge_B5 1023 "Null" ;
VAL_ 2335108764 M2P_SOE_Discharge_B5 1023 "Null" ;
VAL_ 2335108765 M2P_SOE_Charge_B5 1023 "Null" ;
VAL_ 2335108765 M2P_SOE_Discharge_B5 1023 "Null" ;
VAL_ 2335108766 M2P_SOE_Charge_B5 1023 "Null" ;
VAL_ 2335108766 M2P_SOE_Discharge_B5 1023 "Null" ;
VAL_ 2335108767 M2P_SOE_Charge_B5 1023 "Null" ;
VAL_ 2335108767 M2P_SOE_Discharge_B5 1023 "Null" ;
VAL_ 2335108768 M2P_SOE_Charge_B5 1023 "Null" ;
VAL_ 2335108768 M2P_SOE_Discharge_B5 1023 "Null" ;
VAL_ 2335108769 M2P_SOE_Charge_B5 1023 "Null" ;
VAL_ 2335108769 M2P_SOE_Discharge_B5 1023 "Null" ;
VAL_ 2335108770 M2P_SOE_Charge_B5 1023 "Null" ;
VAL_ 2335108770 M2P_SOE_Discharge_B5 1023 "Null" ;
VAL_ 2335108771 M2P_SOE_Charge_B5 1023 "Null" ;
VAL_ 2335108771 M2P_SOE_Discharge_B5 1023 "Null" ;
VAL_ 2335108772 M2P_SOE_Charge_B5 1023 "Null" ;
VAL_ 2335108772 M2P_SOE_Discharge_B5 1023 "Null" ;
VAL_ 2335108773 M2P_SOE_Charge_B5 1023 "Null" ;
VAL_ 2335108773 M2P_SOE_Discharge_B5 1023 "Null" ;
VAL_ 2335108774 M2P_SOE_Charge_B5 1023 "Null" ;
VAL_ 2335108774 M2P_SOE_Discharge_B5 1023 "Null" ;
VAL_ 2335108775 M2P_SOE_Charge_B5 1023 "Null" ;
VAL_ 2335108775 M2P_SOE_Discharge_B5 1023 "Null" ;
VAL_ 2335108776 M2P_SOE_Charge_B5 1023 "Null" ;
VAL_ 2335108776 M2P_SOE_Discharge_B5 1023 "Null" ;
VAL_ 2335108777 M2P_SOE_Charge_B5 1023 "Null" ;
VAL_ 2335108777 M2P_SOE_Discharge_B5 1023 "Null" ;
VAL_ 2335108778 M2P_SOE_Charge_B5 1023 "Null" ;
VAL_ 2335108778 M2P_SOE_Discharge_B5 1023 "Null" ;
VAL_ 2335108779 M2P_SOE_Charge_B5 1023 "Null" ;
VAL_ 2335108779 M2P_SOE_Discharge_B5 1023 "Null" ;
VAL_ 2335108780 M2P_SOE_Charge_B5 1023 "Null" ;
VAL_ 2335108780 M2P_SOE_Discharge_B5 1023 "Null" ;
VAL_ 2335108781 M2P_SOE_Charge_B5 1023 "Null" ;
VAL_ 2335108781 M2P_SOE_Discharge_B5 1023 "Null" ;
VAL_ 2335108782 M2P_SOE_Charge_B5 1023 "Null" ;
VAL_ 2335108782 M2P_SOE_Discharge_B5 1023 "Null" ;
VAL_ 2335108783 M2P_SOE_Charge_B5 1023 "Null" ;
VAL_ 2335108783 M2P_SOE_Discharge_B5 1023 "Null" ;
VAL_ 2335174289 M2P_Measure_Vol_B6_01 65535 "Invalid" ;
VAL_ 2335174289 M2P_Current_B6_01 65535 "Invalid" ;
VAL_ 2335174289 M2P_PermitMaxCharge_I_B6_01 65535 "Invalid" ;
VAL_ 2335174289 M2P_PermitMaxDisCharge_I_B6_01 65535 "Invalid" ;
VAL_ 2335174290 M2P_Measure_Vol_B6_02 65535 "Invalid" ;
VAL_ 2335174290 M2P_Current_B6_02 65535 "Invalid" ;
VAL_ 2335174290 M2P_PermitMaxCharge_I_B6_02 65535 "Invalid" ;
VAL_ 2335174290 M2P_PermitMaxDisCharge_I_B6_02 65535 "Invalid" ;
VAL_ 2335174291 M2P_Measure_Vol_B6_03 65535 "Invalid" ;
VAL_ 2335174291 M2P_Current_B6_03 65535 "Invalid" ;
VAL_ 2335174291 M2P_PermitMaxCharge_I_B6_03 65535 "Invalid" ;
VAL_ 2335174291 M2P_PermitMaxDisCharge_I_B6_03 65535 "Invalid" ;
VAL_ 2335174292 M2P_Measure_Vol_B6_04 65535 "Invalid" ;
VAL_ 2335174292 M2P_Current_B6_04 65535 "Invalid" ;
VAL_ 2335174292 M2P_PermitMaxCharge_I_B6_04 65535 "Invalid" ;
VAL_ 2335174292 M2P_PermitMaxDisCharge_I_B6_04 65535 "Invalid" ;
VAL_ 2335174293 M2P_Measure_Vol_B6_05 65535 "Invalid" ;
VAL_ 2335174293 M2P_Current_B6_05 65535 "Invalid" ;
VAL_ 2335174293 M2P_PermitMaxCharge_I_B6_05 65535 "Invalid" ;
VAL_ 2335174293 M2P_PermitMaxDisCharge_I_B6_05 65535 "Invalid" ;
VAL_ 2335174294 M2P_Measure_Vol_B6_06 65535 "Invalid" ;
VAL_ 2335174294 M2P_Current_B6_06 65535 "Invalid" ;
VAL_ 2335174294 M2P_PermitMaxCharge_I_B6_06 65535 "Invalid" ;
VAL_ 2335174294 M2P_PermitMaxDisCharge_I_B6_06 65535 "Invalid" ;
VAL_ 2335174295 M2P_Measure_Vol_B6_07 65535 "Invalid" ;
VAL_ 2335174295 M2P_Current_B6_07 65535 "Invalid" ;
VAL_ 2335174295 M2P_PermitMaxCharge_I_B6_07 65535 "Invalid" ;
VAL_ 2335174295 M2P_PermitMaxDisCharge_I_B6_07 65535 "Invalid" ;
VAL_ 2335174296 M2P_Measure_Vol_B6_08 65535 "Invalid" ;
VAL_ 2335174296 M2P_Current_B6_08 65535 "Invalid" ;
VAL_ 2335174296 M2P_PermitMaxCharge_I_B6_08 65535 "Invalid" ;
VAL_ 2335174296 M2P_PermitMaxDisCharge_I_B6_08 65535 "Invalid" ;
VAL_ 2335174297 M2P_Measure_Vol_B6_09 65535 "Invalid" ;
VAL_ 2335174297 M2P_Current_B6_09 65535 "Invalid" ;
VAL_ 2335174297 M2P_PermitMaxCharge_I_B6_09 65535 "Invalid" ;
VAL_ 2335174297 M2P_PermitMaxDisCharge_I_B6_09 65535 "Invalid" ;
VAL_ 2335174298 M2P_Measure_Vol_B6_10 65535 "Invalid" ;
VAL_ 2335174298 M2P_Current_B6_10 65535 "Invalid" ;
VAL_ 2335174298 M2P_PermitMaxCharge_I_B6_10 65535 "Invalid" ;
VAL_ 2335174298 M2P_PermitMaxDisCharge_I_B6_10 65535 "Invalid" ;
VAL_ 2335174299 M2P_Measure_Vol_B6_11 65535 "Invalid" ;
VAL_ 2335174299 M2P_Current_B6_11 65535 "Invalid" ;
VAL_ 2335174299 M2P_PermitMaxCharge_I_B6_11 65535 "Invalid" ;
VAL_ 2335174299 M2P_PermitMaxDisCharge_I_B6_11 65535 "Invalid" ;
VAL_ 2335174300 M2P_Measure_Vol_B6_12 65535 "Invalid" ;
VAL_ 2335174300 M2P_Current_B6_12 65535 "Invalid" ;
VAL_ 2335174300 M2P_PermitMaxCharge_I_B6_12 65535 "Invalid" ;
VAL_ 2335174300 M2P_PermitMaxDisCharge_I_B6_12 65535 "Invalid" ;
VAL_ 2335174301 M2P_Measure_Vol_B6_13 65535 "Invalid" ;
VAL_ 2335174301 M2P_Current_B6_13 65535 "Invalid" ;
VAL_ 2335174301 M2P_PermitMaxCharge_I_B6_13 65535 "Invalid" ;
VAL_ 2335174301 M2P_PermitMaxDisCharge_I_B6_13 65535 "Invalid" ;
VAL_ 2335174302 M2P_Measure_Vol_B6_14 65535 "Invalid" ;
VAL_ 2335174302 M2P_Current_B6_14 65535 "Invalid" ;
VAL_ 2335174302 M2P_PermitMaxCharge_I_B6_14 65535 "Invalid" ;
VAL_ 2335174302 M2P_PermitMaxDisCharge_I_B6_14 65535 "Invalid" ;
VAL_ 2335174303 M2P_Measure_Vol_B6_15 65535 "Invalid" ;
VAL_ 2335174303 M2P_Current_B6_15 65535 "Invalid" ;
VAL_ 2335174303 M2P_PermitMaxCharge_I_B6_15 65535 "Invalid" ;
VAL_ 2335174303 M2P_PermitMaxDisCharge_I_B6_15 65535 "Invalid" ;
VAL_ 2335174304 M2P_Measure_Vol_B6_16 65535 "Invalid" ;
VAL_ 2335174304 M2P_Current_B6_16 65535 "Invalid" ;
VAL_ 2335174304 M2P_PermitMaxCharge_I_B6_16 65535 "Invalid" ;
VAL_ 2335174304 M2P_PermitMaxDisCharge_I_B6_16 65535 "Invalid" ;
VAL_ 2335174305 M2P_Measure_Vol_B6_17 65535 "Invalid" ;
VAL_ 2335174305 M2P_Current_B6_17 65535 "Invalid" ;
VAL_ 2335174305 M2P_PermitMaxCharge_I_B6_17 65535 "Invalid" ;
VAL_ 2335174305 M2P_PermitMaxDisCharge_I_B6_17 65535 "Invalid" ;
VAL_ 2335174306 M2P_Measure_Vol_B6_18 65535 "Invalid" ;
VAL_ 2335174306 M2P_Current_B6_18 65535 "Invalid" ;
VAL_ 2335174306 M2P_PermitMaxCharge_I_B6_18 65535 "Invalid" ;
VAL_ 2335174306 M2P_PermitMaxDisCharge_I_B6_18 65535 "Invalid" ;
VAL_ 2335174307 M2P_Measure_Vol_B6_19 65535 "Invalid" ;
VAL_ 2335174307 M2P_Current_B6_19 65535 "Invalid" ;
VAL_ 2335174307 M2P_PermitMaxCharge_I_B6_19 65535 "Invalid" ;
VAL_ 2335174307 M2P_PermitMaxDisCharge_I_B6_19 65535 "Invalid" ;
VAL_ 2335174308 M2P_Measure_Vol_B6_20 65535 "Invalid" ;
VAL_ 2335174308 M2P_Current_B6_20 65535 "Invalid" ;
VAL_ 2335174308 M2P_PermitMaxCharge_I_B6_20 65535 "Invalid" ;
VAL_ 2335174308 M2P_PermitMaxDisCharge_I_B6_20 65535 "Invalid" ;
VAL_ 2335174309 M2P_Measure_Vol_B6_21 65535 "Invalid" ;
VAL_ 2335174309 M2P_Current_B6_21 65535 "Invalid" ;
VAL_ 2335174309 M2P_PermitMaxCharge_I_B6_21 65535 "Invalid" ;
VAL_ 2335174309 M2P_PermitMaxDisCharge_I_B6_21 65535 "Invalid" ;
VAL_ 2335174310 M2P_Measure_Vol_B6_22 65535 "Invalid" ;
VAL_ 2335174310 M2P_Current_B6_22 65535 "Invalid" ;
VAL_ 2335174310 M2P_PermitMaxCharge_I_B6_22 65535 "Invalid" ;
VAL_ 2335174310 M2P_PermitMaxDisCharge_I_B6_22 65535 "Invalid" ;
VAL_ 2335174311 M2P_Measure_Vol_B6_23 65535 "Invalid" ;
VAL_ 2335174311 M2P_Current_B6_23 65535 "Invalid" ;
VAL_ 2335174311 M2P_PermitMaxCharge_I_B6_23 65535 "Invalid" ;
VAL_ 2335174311 M2P_PermitMaxDisCharge_I_B6_23 65535 "Invalid" ;
VAL_ 2335174312 M2P_Measure_Vol_B6_24 65535 "Invalid" ;
VAL_ 2335174312 M2P_Current_B6_24 65535 "Invalid" ;
VAL_ 2335174312 M2P_PermitMaxCharge_I_B6_24 65535 "Invalid" ;
VAL_ 2335174312 M2P_PermitMaxDisCharge_I_B6_24 65535 "Invalid" ;
VAL_ 2335174313 M2P_Measure_Vol_B6_25 65535 "Invalid" ;
VAL_ 2335174313 M2P_Current_B6_25 65535 "Invalid" ;
VAL_ 2335174313 M2P_PermitMaxCharge_I_B6_25 65535 "Invalid" ;
VAL_ 2335174313 M2P_PermitMaxDisCharge_I_B6_25 65535 "Invalid" ;
VAL_ 2335174314 M2P_Measure_Vol_B6_26 65535 "Invalid" ;
VAL_ 2335174314 M2P_Current_B6_26 65535 "Invalid" ;
VAL_ 2335174314 M2P_PermitMaxCharge_I_B6_26 65535 "Invalid" ;
VAL_ 2335174314 M2P_PermitMaxDisCharge_I_B6_26 65535 "Invalid" ;
VAL_ 2335174315 M2P_Measure_Vol_B6_27 65535 "Invalid" ;
VAL_ 2335174315 M2P_Current_B6_27 65535 "Invalid" ;
VAL_ 2335174315 M2P_PermitMaxCharge_I_B6_27 65535 "Invalid" ;
VAL_ 2335174315 M2P_PermitMaxDisCharge_I_B6_27 65535 "Invalid" ;
VAL_ 2335174316 M2P_Measure_Vol_B6_28 65535 "Invalid" ;
VAL_ 2335174316 M2P_Current_B6_28 65535 "Invalid" ;
VAL_ 2335174316 M2P_PermitMaxCharge_I_B6_28 65535 "Invalid" ;
VAL_ 2335174316 M2P_PermitMaxDisCharge_I_B6_28 65535 "Invalid" ;
VAL_ 2335174317 M2P_Measure_Vol_B6_29 65535 "Invalid" ;
VAL_ 2335174317 M2P_Current_B6_29 65535 "Invalid" ;
VAL_ 2335174317 M2P_PermitMaxCharge_I_B6_29 65535 "Invalid" ;
VAL_ 2335174317 M2P_PermitMaxDisCharge_I_B6_29 65535 "Invalid" ;
VAL_ 2335174318 M2P_Measure_Vol_B6_30 65535 "Invalid" ;
VAL_ 2335174318 M2P_Current_B6_30 65535 "Invalid" ;
VAL_ 2335174318 M2P_PermitMaxCharge_I_B6_30 65535 "Invalid" ;
VAL_ 2335174318 M2P_PermitMaxDisCharge_I_B6_30 65535 "Invalid" ;
VAL_ 2335174319 M2P_Measure_Vol_B6_31 65535 "Invalid" ;
VAL_ 2335174319 M2P_Current_B6_31 65535 "Invalid" ;
VAL_ 2335174319 M2P_PermitMaxCharge_I_B6_31 65535 "Invalid" ;
VAL_ 2335174319 M2P_PermitMaxDisCharge_I_B6_31 65535 "Invalid" ;
VAL_ 2335305361 M2P_SysremEngy_Chg_B6_01 65535 "Invalid" ;
VAL_ 2335305361 M2P_SysremEngy_DisChg_B6_01 65535 "Invalid" ;
VAL_ 2335305362 M2P_SysremEngy_Chg_B6_02 65535 "Invalid" ;
VAL_ 2335305362 M2P_SysremEngy_DisChg_B6_02 65535 "Invalid" ;
VAL_ 2335305363 M2P_SysremEngy_Chg_B6_03 65535 "Invalid" ;
VAL_ 2335305363 M2P_SysremEngy_DisChg_B6_03 65535 "Invalid" ;
VAL_ 2335305364 M2P_SysremEngy_Chg_B6_04 65535 "Invalid" ;
VAL_ 2335305364 M2P_SysremEngy_DisChg_B6_04 65535 "Invalid" ;
VAL_ 2335305365 M2P_SysremEngy_Chg_B6_05 65535 "Invalid" ;
VAL_ 2335305365 M2P_SysremEngy_DisChg_B6_05 65535 "Invalid" ;
VAL_ 2335305366 M2P_SysremEngy_Chg_B6_06 65535 "Invalid" ;
VAL_ 2335305366 M2P_SysremEngy_DisChg_B6_06 65535 "Invalid" ;
VAL_ 2335305367 M2P_SysremEngy_Chg_B6_07 65535 "Invalid" ;
VAL_ 2335305367 M2P_SysremEngy_DisChg_B6_07 65535 "Invalid" ;
VAL_ 2335305368 M2P_SysremEngy_Chg_B6_08 65535 "Invalid" ;
VAL_ 2335305368 M2P_SysremEngy_DisChg_B6_08 65535 "Invalid" ;
VAL_ 2335305369 M2P_SysremEngy_Chg_B6_09 65535 "Invalid" ;
VAL_ 2335305369 M2P_SysremEngy_DisChg_B6_09 65535 "Invalid" ;
VAL_ 2335305370 M2P_SysremEngy_Chg_B6_10 65535 "Invalid" ;
VAL_ 2335305370 M2P_SysremEngy_DisChg_B6_10 65535 "Invalid" ;
VAL_ 2335305371 M2P_SysremEngy_Chg_B6_11 65535 "Invalid" ;
VAL_ 2335305371 M2P_SysremEngy_DisChg_B6_11 65535 "Invalid" ;
VAL_ 2335305372 M2P_SysremEngy_Chg_B6_12 65535 "Invalid" ;
VAL_ 2335305372 M2P_SysremEngy_DisChg_B6_12 65535 "Invalid" ;
VAL_ 2335305373 M2P_SysremEngy_Chg_B6_13 65535 "Invalid" ;
VAL_ 2335305373 M2P_SysremEngy_DisChg_B6_13 65535 "Invalid" ;
VAL_ 2335305374 M2P_SysremEngy_Chg_B6_14 65535 "Invalid" ;
VAL_ 2335305374 M2P_SysremEngy_DisChg_B6_14 65535 "Invalid" ;
VAL_ 2335305375 M2P_SysremEngy_Chg_B6_15 65535 "Invalid" ;
VAL_ 2335305375 M2P_SysremEngy_DisChg_B6_15 65535 "Invalid" ;
VAL_ 2335305376 M2P_SysremEngy_Chg_B6_16 65535 "Invalid" ;
VAL_ 2335305376 M2P_SysremEngy_DisChg_B6_16 65535 "Invalid" ;
VAL_ 2335305377 M2P_SysremEngy_Chg_B6_17 65535 "Invalid" ;
VAL_ 2335305377 M2P_SysremEngy_DisChg_B6_17 65535 "Invalid" ;
VAL_ 2335305378 M2P_SysremEngy_Chg_B6_18 65535 "Invalid" ;
VAL_ 2335305378 M2P_SysremEngy_DisChg_B6_18 65535 "Invalid" ;
VAL_ 2335305379 M2P_SysremEngy_Chg_B6_19 65535 "Invalid" ;
VAL_ 2335305379 M2P_SysremEngy_DisChg_B6_19 65535 "Invalid" ;
VAL_ 2335305380 M2P_SysremEngy_Chg_B6_20 65535 "Invalid" ;
VAL_ 2335305380 M2P_SysremEngy_DisChg_B6_20 65535 "Invalid" ;
VAL_ 2335305381 M2P_SysremEngy_Chg_B6_21 65535 "Invalid" ;
VAL_ 2335305381 M2P_SysremEngy_DisChg_B6_21 65535 "Invalid" ;
VERSION ""

NS_ :

BS_:

BU_: MBMU PC SBMU IMM ETH DCDC LEMS

BO_ 2335305382 M2P_SUMDATA42__22: 8 MBMU
 SG_ M2P_Power_B6_22 : 0|16@1+ (1,-20000) [-20000|45535] "Kw"  PC
 SG_ M2P_SysremEngy_Chg_B6_22 : 16|16@1+ (1,0) [0|65535] "Kwh"  PC
 SG_ M2P_SysremEngy_DisChg_B6_22 : 32|16@1+ (1,0) [0|65535] "Kwh"  PC
 SG_ M2P_SysMaxVolt_B6_22 : 48|16@1+ (1,0) [0|65535] "mv"  PC

BO_ 2335305383 M2P_SUMDATA42__23: 8 MBMU
 SG_ M2P_Power_B6_23 : 0|16@1+ (1,-20000) [-20000|45535] "Kw"  PC
 SG_ M2P_SysremEngy_Chg_B6_23 : 16|16@1+ (1,0) [0|65535] "Kwh"  PC
 SG_ M2P_SysremEngy_DisChg_B6_23 : 32|16@1+ (1,0) [0|65535] "Kwh"  PC
 SG_ M2P_SysMaxVolt_B6_23 : 48|16@1+ (1,0) [0|65535] "mv"  PC

BO_ 2335305384 M2P_SUMDATA42__24: 8 MBMU
 SG_ M2P_Power_B6_24 : 0|16@1+ (1,-20000) [-20000|45535] "Kw"  PC
 SG_ M2P_SysremEngy_Chg_B6_24 : 16|16@1+ (1,0) [0|65535] "Kwh"  PC
 SG_ M2P_SysremEngy_DisChg_B6_24 : 32|16@1+ (1,0) [0|65535] "Kwh"  PC
 SG_ M2P_SysMaxVolt_B6_24 : 48|16@1+ (1,0) [0|65535] "mv"  PC

BO_ 2335305385 M2P_SUMDATA42__25: 8 MBMU
 SG_ M2P_Power_B6_25 : 0|16@1+ (1,-20000) [-20000|45535] "Kw"  PC
 SG_ M2P_SysremEngy_Chg_B6_25 : 16|16@1+ (1,0) [0|65535] "Kwh"  PC
 SG_ M2P_SysremEngy_DisChg_B6_25 : 32|16@1+ (1,0) [0|65535] "Kwh"  PC
 SG_ M2P_SysMaxVolt_B6_25 : 48|16@1+ (1,0) [0|65535] "mv"  PC

BO_ 2335305386 M2P_SUMDATA42__26: 8 MBMU
 SG_ M2P_Power_B6_26 : 0|16@1+ (1,-20000) [-20000|45535] "Kw"  PC
 SG_ M2P_SysremEngy_Chg_B6_26 : 16|16@1+ (1,0) [0|65535] "Kwh"  PC
 SG_ M2P_SysremEngy_DisChg_B6_26 : 32|16@1+ (1,0) [0|65535] "Kwh"  PC
 SG_ M2P_SysMaxVolt_B6_26 : 48|16@1+ (1,0) [0|65535] "mv"  PC

BO_ 2335305387 M2P_SUMDATA42__27: 8 MBMU
 SG_ M2P_Power_B6_27 : 0|16@1+ (1,-20000) [-20000|45535] "Kw"  PC
 SG_ M2P_SysremEngy_Chg_B6_27 : 16|16@1+ (1,0) [0|65535] "Kwh"  PC
 SG_ M2P_SysremEngy_DisChg_B6_27 : 32|16@1+ (1,0) [0|65535] "Kwh"  PC
 SG_ M2P_SysMaxVolt_B6_27 : 48|16@1+ (1,0) [0|65535] "mv"  PC

BO_ 2335305388 M2P_SUMDATA42__28: 8 MBMU
 SG_ M2P_Power_B6_28 : 0|16@1+ (1,-20000) [-20000|45535] "Kw"  PC
 SG_ M2P_SysremEngy_Chg_B6_28 : 16|16@1+ (1,0) [0|65535] "Kwh"  PC
 SG_ M2P_SysremEngy_DisChg_B6_28 : 32|16@1+ (1,0) [0|65535] "Kwh"  PC
 SG_ M2P_SysMaxVolt_B6_28 : 48|16@1+ (1,0) [0|65535] "mv"  PC

BO_ 2335305389 M2P_SUMDATA42__29: 8 MBMU
 SG_ M2P_Power_B6_29 : 0|16@1+ (1,-20000) [-20000|45535] "Kw"  PC
 SG_ M2P_SysremEngy_Chg_B6_29 : 16|16@1+ (1,0) [0|65535] "Kwh"  PC
 SG_ M2P_SysremEngy_DisChg_B6_29 : 32|16@1+ (1,0) [0|65535] "Kwh"  PC
 SG_ M2P_SysMaxVolt_B6_29 : 48|16@1+ (1,0) [0|65535] "mv"  PC

BO_ 2335305390 M2P_SUMDATA42__30: 8 MBMU
 SG_ M2P_Power_B6_30 : 0|16@1+ (1,-20000) [-20000|45535] "Kw"  PC
 SG_ M2P_SysremEngy_Chg_B6_30 : 16|16@1+ (1,0) [0|65535] "Kwh"  PC
 SG_ M2P_SysremEngy_DisChg_B6_30 : 32|16@1+ (1,0) [0|65535] "Kwh"  PC
 SG_ M2P_SysMaxVolt_B6_30 : 48|16@1+ (1,0) [0|65535] "mv"  PC

BO_ 2335305391 M2P_SUMDATA42__31: 8 MBMU
 SG_ M2P_Power_B6_31 : 0|16@1+ (1,-20000) [-20000|45535] "Kw"  PC
 SG_ M2P_SysremEngy_Chg_B6_31 : 16|16@1+ (1,0) [0|65535] "Kwh"  PC
 SG_ M2P_SysremEngy_DisChg_B6_31 : 32|16@1+ (1,0) [0|65535] "Kwh"  PC
 SG_ M2P_SysMaxVolt_B6_31 : 48|16@1+ (1,0) [0|65535] "mv"  PC

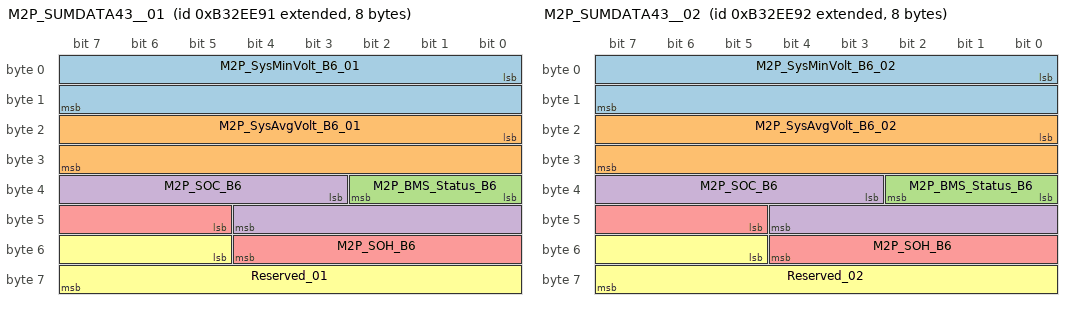
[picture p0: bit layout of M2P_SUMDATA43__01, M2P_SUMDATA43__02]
BO_ 2335370897 M2P_SUMDATA43__01: 8 MBMU
 SG_ M2P_SysMinVolt_B6_01 : 0|16@1+ (1,0) [0|65535] "mv"  PC
 SG_ M2P_SysAvgVolt_B6_01 : 16|16@1+ (1,0) [0|65535] "mv"  PC
 SG_ M2P_BMS_Status_B6 : 32|3@1+ (1,0) [0|7] ""  PC
 SG_ M2P_SOC_B6 : 35|10@1+ (0.1,0) [0|102.3] "%"  PC
 SG_ M2P_SOH_B6 : 45|8@1+ (1,0) [0|255] "%"  PC
 SG_ Reserved_01 : 53|11@1+ (1,0) [0|2047] ""  PC

BO_ 2335370898 M2P_SUMDATA43__02: 8 MBMU
 SG_ M2P_SysMinVolt_B6_02 : 0|16@1+ (1,0) [0|65535] "mv"  PC
 SG_ M2P_SysAvgVolt_B6_02 : 16|16@1+ (1,0) [0|65535] "mv"  PC
 SG_ M2P_BMS_Status_B6 : 32|3@1+ (1,0) [0|7] ""  PC
 SG_ M2P_SOC_B6 : 35|10@1+ (0.1,0) [0|102.3] "%"  PC
 SG_ M2P_SOH_B6 : 45|8@1+ (1,0) [0|255] "%"  PC
 SG_ Reserved_02 : 53|11@1+ (1,0) [0|2047] ""  PC

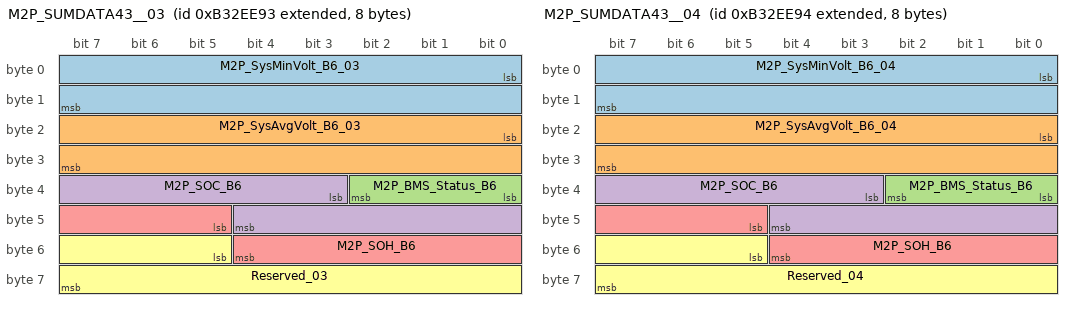
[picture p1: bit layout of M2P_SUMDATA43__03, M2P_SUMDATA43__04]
BO_ 2335370899 M2P_SUMDATA43__03: 8 MBMU
 SG_ M2P_SysMinVolt_B6_03 : 0|16@1+ (1,0) [0|65535] "mv"  PC
 SG_ M2P_SysAvgVolt_B6_03 : 16|16@1+ (1,0) [0|65535] "mv"  PC
 SG_ M2P_BMS_Status_B6 : 32|3@1+ (1,0) [0|7] ""  PC
 SG_ M2P_SOC_B6 : 35|10@1+ (0.1,0) [0|102.3] "%"  PC
 SG_ M2P_SOH_B6 : 45|8@1+ (1,0) [0|255] "%"  PC
 SG_ Reserved_03 : 53|11@1+ (1,0) [0|2047] ""  PC

BO_ 2335370900 M2P_SUMDATA43__04: 8 MBMU
 SG_ M2P_SysMinVolt_B6_04 : 0|16@1+ (1,0) [0|65535] "mv"  PC
 SG_ M2P_SysAvgVolt_B6_04 : 16|16@1+ (1,0) [0|65535] "mv"  PC
 SG_ M2P_BMS_Status_B6 : 32|3@1+ (1,0) [0|7] ""  PC
 SG_ M2P_SOC_B6 : 35|10@1+ (0.1,0) [0|102.3] "%"  PC
 SG_ M2P_SOH_B6 : 45|8@1+ (1,0) [0|255] "%"  PC
 SG_ Reserved_04 : 53|11@1+ (1,0) [0|2047] ""  PC

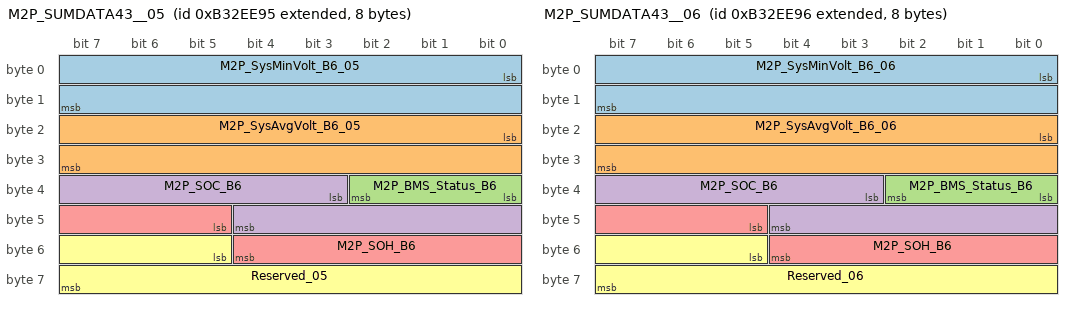
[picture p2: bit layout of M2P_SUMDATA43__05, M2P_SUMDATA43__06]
BO_ 2335370901 M2P_SUMDATA43__05: 8 MBMU
 SG_ M2P_SysMinVolt_B6_05 : 0|16@1+ (1,0) [0|65535] "mv"  PC
 SG_ M2P_SysAvgVolt_B6_05 : 16|16@1+ (1,0) [0|65535] "mv"  PC
 SG_ M2P_BMS_Status_B6 : 32|3@1+ (1,0) [0|7] ""  PC
 SG_ M2P_SOC_B6 : 35|10@1+ (0.1,0) [0|102.3] "%"  PC
 SG_ M2P_SOH_B6 : 45|8@1+ (1,0) [0|255] "%"  PC
 SG_ Reserved_05 : 53|11@1+ (1,0) [0|2047] ""  PC

BO_ 2335370902 M2P_SUMDATA43__06: 8 MBMU
 SG_ M2P_SysMinVolt_B6_06 : 0|16@1+ (1,0) [0|65535] "mv"  PC
 SG_ M2P_SysAvgVolt_B6_06 : 16|16@1+ (1,0) [0|65535] "mv"  PC
 SG_ M2P_BMS_Status_B6 : 32|3@1+ (1,0) [0|7] ""  PC
 SG_ M2P_SOC_B6 : 35|10@1+ (0.1,0) [0|102.3] "%"  PC
 SG_ M2P_SOH_B6 : 45|8@1+ (1,0) [0|255] "%"  PC
 SG_ Reserved_06 : 53|11@1+ (1,0) [0|2047] ""  PC

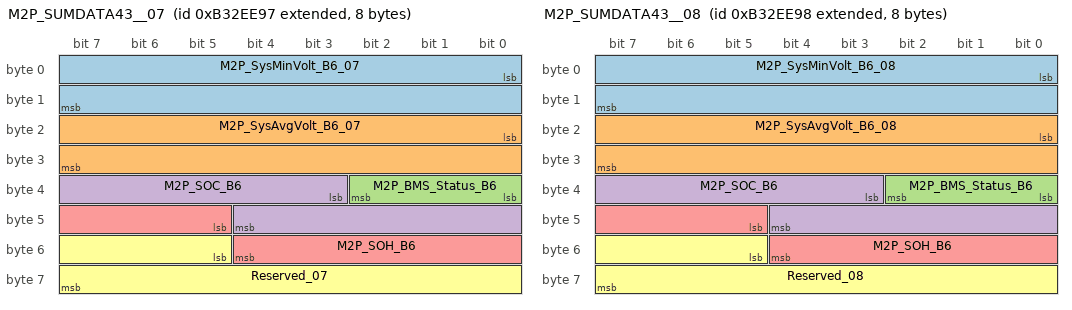
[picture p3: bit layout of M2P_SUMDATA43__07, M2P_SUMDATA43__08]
BO_ 2335370903 M2P_SUMDATA43__07: 8 MBMU
 SG_ M2P_SysMinVolt_B6_07 : 0|16@1+ (1,0) [0|65535] "mv"  PC
 SG_ M2P_SysAvgVolt_B6_07 : 16|16@1+ (1,0) [0|65535] "mv"  PC
 SG_ M2P_BMS_Status_B6 : 32|3@1+ (1,0) [0|7] ""  PC
 SG_ M2P_SOC_B6 : 35|10@1+ (0.1,0) [0|102.3] "%"  PC
 SG_ M2P_SOH_B6 : 45|8@1+ (1,0) [0|255] "%"  PC
 SG_ Reserved_07 : 53|11@1+ (1,0) [0|2047] ""  PC

BO_ 2335370904 M2P_SUMDATA43__08: 8 MBMU
 SG_ M2P_SysMinVolt_B6_08 : 0|16@1+ (1,0) [0|65535] "mv"  PC
 SG_ M2P_SysAvgVolt_B6_08 : 16|16@1+ (1,0) [0|65535] "mv"  PC
 SG_ M2P_BMS_Status_B6 : 32|3@1+ (1,0) [0|7] ""  PC
 SG_ M2P_SOC_B6 : 35|10@1+ (0.1,0) [0|102.3] "%"  PC
 SG_ M2P_SOH_B6 : 45|8@1+ (1,0) [0|255] "%"  PC
 SG_ Reserved_08 : 53|11@1+ (1,0) [0|2047] ""  PC

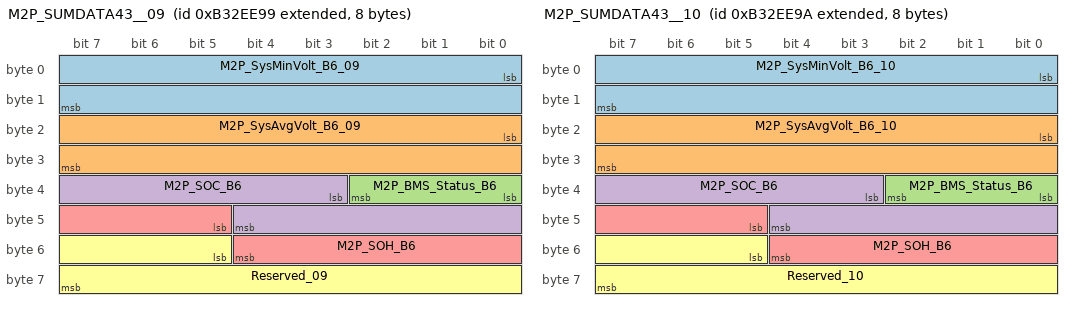
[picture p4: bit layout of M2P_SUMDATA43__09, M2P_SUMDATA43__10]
BO_ 2335370905 M2P_SUMDATA43__09: 8 MBMU
 SG_ M2P_SysMinVolt_B6_09 : 0|16@1+ (1,0) [0|65535] "mv"  PC
 SG_ M2P_SysAvgVolt_B6_09 : 16|16@1+ (1,0) [0|65535] "mv"  PC
 SG_ M2P_BMS_Status_B6 : 32|3@1+ (1,0) [0|7] ""  PC
 SG_ M2P_SOC_B6 : 35|10@1+ (0.1,0) [0|102.3] "%"  PC
 SG_ M2P_SOH_B6 : 45|8@1+ (1,0) [0|255] "%"  PC
 SG_ Reserved_09 : 53|11@1+ (1,0) [0|2047] ""  PC

BO_ 2335370906 M2P_SUMDATA43__10: 8 MBMU
 SG_ M2P_SysMinVolt_B6_10 : 0|16@1+ (1,0) [0|65535] "mv"  PC
 SG_ M2P_SysAvgVolt_B6_10 : 16|16@1+ (1,0) [0|65535] "mv"  PC
 SG_ M2P_BMS_Status_B6 : 32|3@1+ (1,0) [0|7] ""  PC
 SG_ M2P_SOC_B6 : 35|10@1+ (0.1,0) [0|102.3] "%"  PC
 SG_ M2P_SOH_B6 : 45|8@1+ (1,0) [0|255] "%"  PC
 SG_ Reserved_10 : 53|11@1+ (1,0) [0|2047] ""  PC

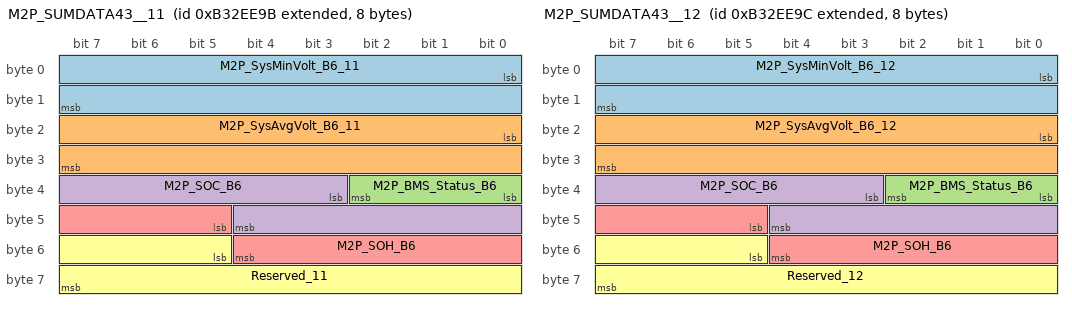
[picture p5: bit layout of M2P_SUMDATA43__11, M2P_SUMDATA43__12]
BO_ 2335370907 M2P_SUMDATA43__11: 8 MBMU
 SG_ M2P_SysMinVolt_B6_11 : 0|16@1+ (1,0) [0|65535] "mv"  PC
 SG_ M2P_SysAvgVolt_B6_11 : 16|16@1+ (1,0) [0|65535] "mv"  PC
 SG_ M2P_BMS_Status_B6 : 32|3@1+ (1,0) [0|7] ""  PC
 SG_ M2P_SOC_B6 : 35|10@1+ (0.1,0) [0|102.3] "%"  PC
 SG_ M2P_SOH_B6 : 45|8@1+ (1,0) [0|255] "%"  PC
 SG_ Reserved_11 : 53|11@1+ (1,0) [0|2047] ""  PC

BO_ 2335370908 M2P_SUMDATA43__12: 8 MBMU
 SG_ M2P_SysMinVolt_B6_12 : 0|16@1+ (1,0) [0|65535] "mv"  PC
 SG_ M2P_SysAvgVolt_B6_12 : 16|16@1+ (1,0) [0|65535] "mv"  PC
 SG_ M2P_BMS_Status_B6 : 32|3@1+ (1,0) [0|7] ""  PC
 SG_ M2P_SOC_B6 : 35|10@1+ (0.1,0) [0|102.3] "%"  PC
 SG_ M2P_SOH_B6 : 45|8@1+ (1,0) [0|255] "%"  PC
 SG_ Reserved_12 : 53|11@1+ (1,0) [0|2047] ""  PC

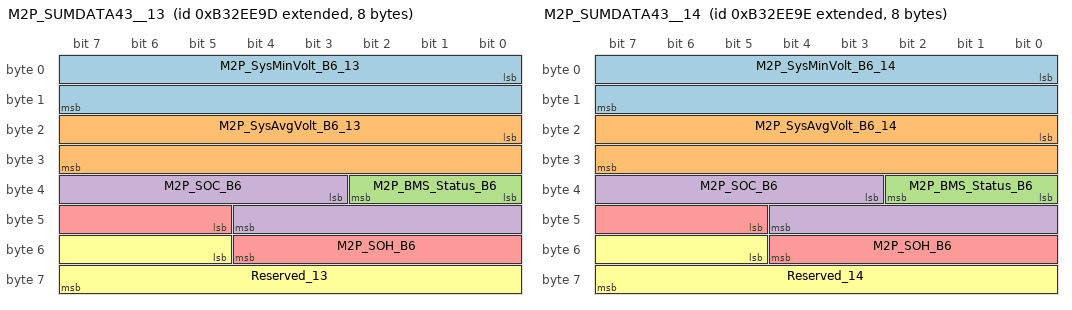
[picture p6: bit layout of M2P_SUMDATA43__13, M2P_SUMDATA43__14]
BO_ 2335370909 M2P_SUMDATA43__13: 8 MBMU
 SG_ M2P_SysMinVolt_B6_13 : 0|16@1+ (1,0) [0|65535] "mv"  PC
 SG_ M2P_SysAvgVolt_B6_13 : 16|16@1+ (1,0) [0|65535] "mv"  PC
 SG_ M2P_BMS_Status_B6 : 32|3@1+ (1,0) [0|7] ""  PC
 SG_ M2P_SOC_B6 : 35|10@1+ (0.1,0) [0|102.3] "%"  PC
 SG_ M2P_SOH_B6 : 45|8@1+ (1,0) [0|255] "%"  PC
 SG_ Reserved_13 : 53|11@1+ (1,0) [0|2047] ""  PC

BO_ 2335370910 M2P_SUMDATA43__14: 8 MBMU
 SG_ M2P_SysMinVolt_B6_14 : 0|16@1+ (1,0) [0|65535] "mv"  PC
 SG_ M2P_SysAvgVolt_B6_14 : 16|16@1+ (1,0) [0|65535] "mv"  PC
 SG_ M2P_BMS_Status_B6 : 32|3@1+ (1,0) [0|7] ""  PC
 SG_ M2P_SOC_B6 : 35|10@1+ (0.1,0) [0|102.3] "%"  PC
 SG_ M2P_SOH_B6 : 45|8@1+ (1,0) [0|255] "%"  PC
 SG_ Reserved_14 : 53|11@1+ (1,0) [0|2047] ""  PC

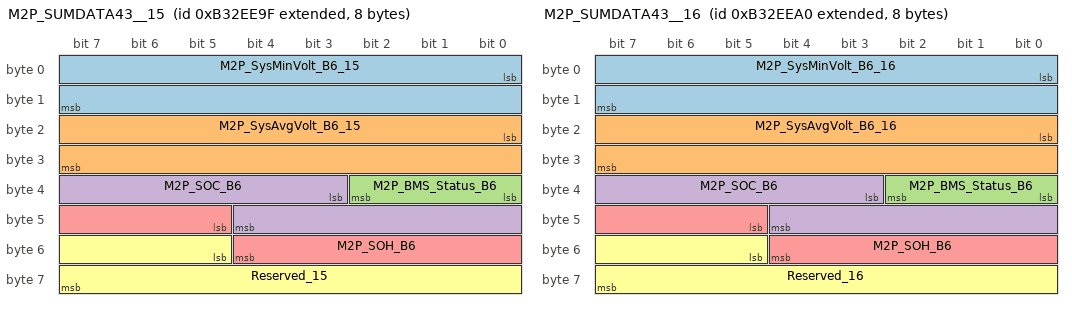
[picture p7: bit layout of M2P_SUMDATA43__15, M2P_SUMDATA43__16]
BO_ 2335370911 M2P_SUMDATA43__15: 8 MBMU
 SG_ M2P_SysMinVolt_B6_15 : 0|16@1+ (1,0) [0|65535] "mv"  PC
 SG_ M2P_SysAvgVolt_B6_15 : 16|16@1+ (1,0) [0|65535] "mv"  PC
 SG_ M2P_BMS_Status_B6 : 32|3@1+ (1,0) [0|7] ""  PC
 SG_ M2P_SOC_B6 : 35|10@1+ (0.1,0) [0|102.3] "%"  PC
 SG_ M2P_SOH_B6 : 45|8@1+ (1,0) [0|255] "%"  PC
 SG_ Reserved_15 : 53|11@1+ (1,0) [0|2047] ""  PC

BO_ 2335370912 M2P_SUMDATA43__16: 8 MBMU
 SG_ M2P_SysMinVolt_B6_16 : 0|16@1+ (1,0) [0|65535] "mv"  PC
 SG_ M2P_SysAvgVolt_B6_16 : 16|16@1+ (1,0) [0|65535] "mv"  PC
 SG_ M2P_BMS_Status_B6 : 32|3@1+ (1,0) [0|7] ""  PC
 SG_ M2P_SOC_B6 : 35|10@1+ (0.1,0) [0|102.3] "%"  PC
 SG_ M2P_SOH_B6 : 45|8@1+ (1,0) [0|255] "%"  PC
 SG_ Reserved_16 : 53|11@1+ (1,0) [0|2047] ""  PC

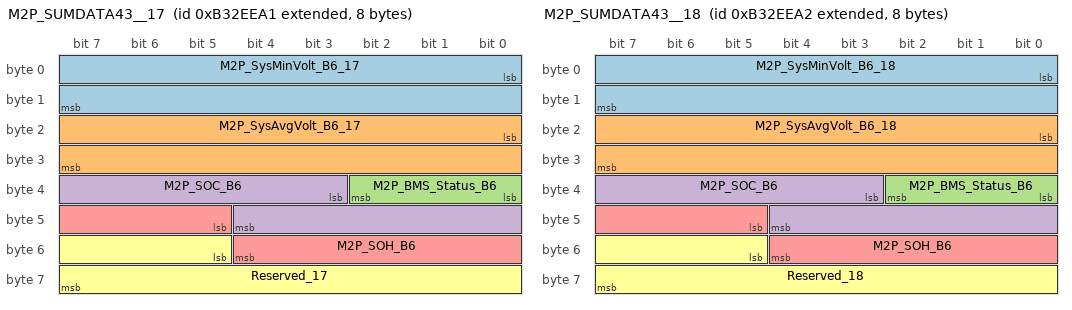
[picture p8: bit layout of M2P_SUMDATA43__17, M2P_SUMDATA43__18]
BO_ 2335370913 M2P_SUMDATA43__17: 8 MBMU
 SG_ M2P_SysMinVolt_B6_17 : 0|16@1+ (1,0) [0|65535] "mv"  PC
 SG_ M2P_SysAvgVolt_B6_17 : 16|16@1+ (1,0) [0|65535] "mv"  PC
 SG_ M2P_BMS_Status_B6 : 32|3@1+ (1,0) [0|7] ""  PC
 SG_ M2P_SOC_B6 : 35|10@1+ (0.1,0) [0|102.3] "%"  PC
 SG_ M2P_SOH_B6 : 45|8@1+ (1,0) [0|255] "%"  PC
 SG_ Reserved_17 : 53|11@1+ (1,0) [0|2047] ""  PC

BO_ 2335370914 M2P_SUMDATA43__18: 8 MBMU
 SG_ M2P_SysMinVolt_B6_18 : 0|16@1+ (1,0) [0|65535] "mv"  PC
 SG_ M2P_SysAvgVolt_B6_18 : 16|16@1+ (1,0) [0|65535] "mv"  PC
 SG_ M2P_BMS_Status_B6 : 32|3@1+ (1,0) [0|7] ""  PC
 SG_ M2P_SOC_B6 : 35|10@1+ (0.1,0) [0|102.3] "%"  PC
 SG_ M2P_SOH_B6 : 45|8@1+ (1,0) [0|255] "%"  PC
 SG_ Reserved_18 : 53|11@1+ (1,0) [0|2047] ""  PC

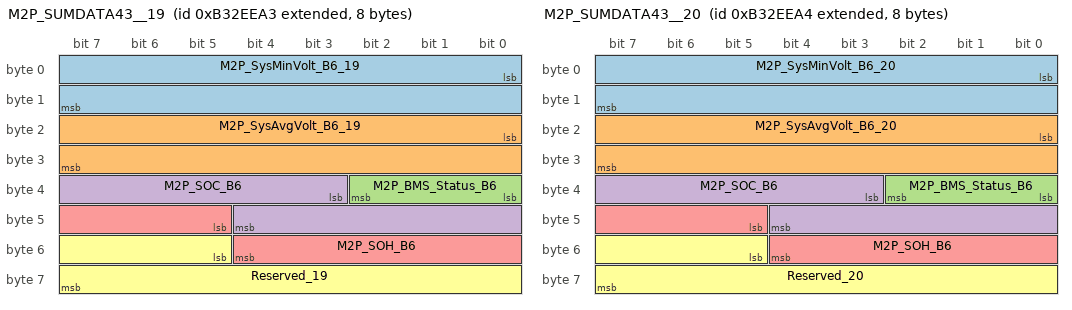
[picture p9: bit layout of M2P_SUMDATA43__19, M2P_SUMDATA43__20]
BO_ 2335370915 M2P_SUMDATA43__19: 8 MBMU
 SG_ M2P_SysMinVolt_B6_19 : 0|16@1+ (1,0) [0|65535] "mv"  PC
 SG_ M2P_SysAvgVolt_B6_19 : 16|16@1+ (1,0) [0|65535] "mv"  PC
 SG_ M2P_BMS_Status_B6 : 32|3@1+ (1,0) [0|7] ""  PC
 SG_ M2P_SOC_B6 : 35|10@1+ (0.1,0) [0|102.3] "%"  PC
 SG_ M2P_SOH_B6 : 45|8@1+ (1,0) [0|255] "%"  PC
 SG_ Reserved_19 : 53|11@1+ (1,0) [0|2047] ""  PC

BO_ 2335370916 M2P_SUMDATA43__20: 8 MBMU
 SG_ M2P_SysMinVolt_B6_20 : 0|16@1+ (1,0) [0|65535] "mv"  PC
 SG_ M2P_SysAvgVolt_B6_20 : 16|16@1+ (1,0) [0|65535] "mv"  PC
 SG_ M2P_BMS_Status_B6 : 32|3@1+ (1,0) [0|7] ""  PC
 SG_ M2P_SOC_B6 : 35|10@1+ (0.1,0) [0|102.3] "%"  PC
 SG_ M2P_SOH_B6 : 45|8@1+ (1,0) [0|255] "%"  PC
 SG_ Reserved_20 : 53|11@1+ (1,0) [0|2047] ""  PC

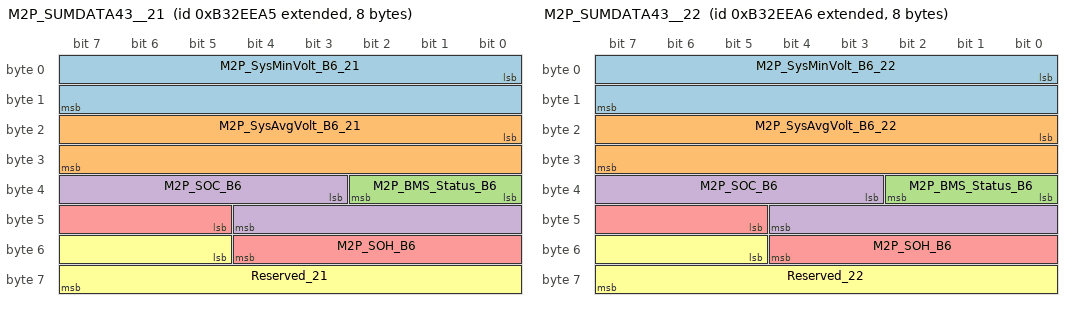
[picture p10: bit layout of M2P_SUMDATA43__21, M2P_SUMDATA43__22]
BO_ 2335370917 M2P_SUMDATA43__21: 8 MBMU
 SG_ M2P_SysMinVolt_B6_21 : 0|16@1+ (1,0) [0|65535] "mv"  PC
 SG_ M2P_SysAvgVolt_B6_21 : 16|16@1+ (1,0) [0|65535] "mv"  PC
 SG_ M2P_BMS_Status_B6 : 32|3@1+ (1,0) [0|7] ""  PC
 SG_ M2P_SOC_B6 : 35|10@1+ (0.1,0) [0|102.3] "%"  PC
 SG_ M2P_SOH_B6 : 45|8@1+ (1,0) [0|255] "%"  PC
 SG_ Reserved_21 : 53|11@1+ (1,0) [0|2047] ""  PC

BO_ 2335370918 M2P_SUMDATA43__22: 8 MBMU
 SG_ M2P_SysMinVolt_B6_22 : 0|16@1+ (1,0) [0|65535] "mv"  PC
 SG_ M2P_SysAvgVolt_B6_22 : 16|16@1+ (1,0) [0|65535] "mv"  PC
 SG_ M2P_BMS_Status_B6 : 32|3@1+ (1,0) [0|7] ""  PC
 SG_ M2P_SOC_B6 : 35|10@1+ (0.1,0) [0|102.3] "%"  PC
 SG_ M2P_SOH_B6 : 45|8@1+ (1,0) [0|255] "%"  PC
 SG_ Reserved_22 : 53|11@1+ (1,0) [0|2047] ""  PC

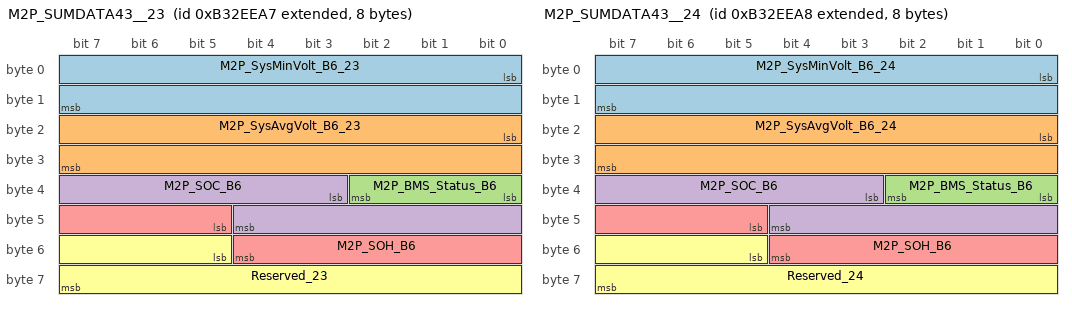
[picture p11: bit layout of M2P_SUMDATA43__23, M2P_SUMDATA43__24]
BO_ 2335370919 M2P_SUMDATA43__23: 8 MBMU
 SG_ M2P_SysMinVolt_B6_23 : 0|16@1+ (1,0) [0|65535] "mv"  PC
 SG_ M2P_SysAvgVolt_B6_23 : 16|16@1+ (1,0) [0|65535] "mv"  PC
 SG_ M2P_BMS_Status_B6 : 32|3@1+ (1,0) [0|7] ""  PC
 SG_ M2P_SOC_B6 : 35|10@1+ (0.1,0) [0|102.3] "%"  PC
 SG_ M2P_SOH_B6 : 45|8@1+ (1,0) [0|255] "%"  PC
 SG_ Reserved_23 : 53|11@1+ (1,0) [0|2047] ""  PC

BO_ 2335370920 M2P_SUMDATA43__24: 8 MBMU
 SG_ M2P_SysMinVolt_B6_24 : 0|16@1+ (1,0) [0|65535] "mv"  PC
 SG_ M2P_SysAvgVolt_B6_24 : 16|16@1+ (1,0) [0|65535] "mv"  PC
 SG_ M2P_BMS_Status_B6 : 32|3@1+ (1,0) [0|7] ""  PC
 SG_ M2P_SOC_B6 : 35|10@1+ (0.1,0) [0|102.3] "%"  PC
 SG_ M2P_SOH_B6 : 45|8@1+ (1,0) [0|255] "%"  PC
 SG_ Reserved_24 : 53|11@1+ (1,0) [0|2047] ""  PC

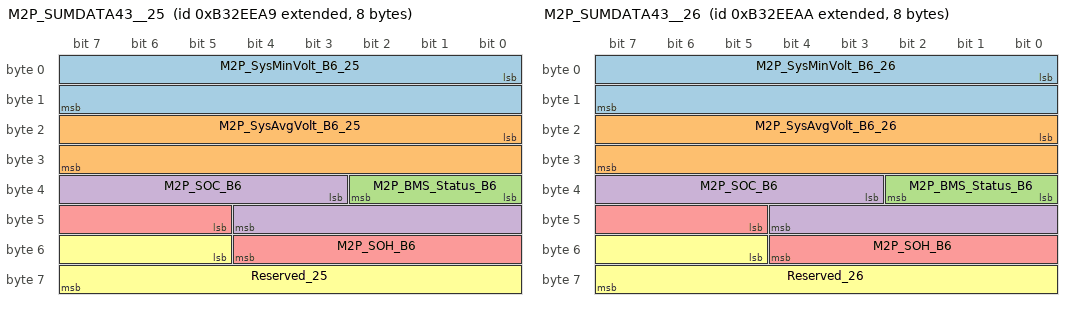
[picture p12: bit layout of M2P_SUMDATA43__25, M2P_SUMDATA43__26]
BO_ 2335370921 M2P_SUMDATA43__25: 8 MBMU
 SG_ M2P_SysMinVolt_B6_25 : 0|16@1+ (1,0) [0|65535] "mv"  PC
 SG_ M2P_SysAvgVolt_B6_25 : 16|16@1+ (1,0) [0|65535] "mv"  PC
 SG_ M2P_BMS_Status_B6 : 32|3@1+ (1,0) [0|7] ""  PC
 SG_ M2P_SOC_B6 : 35|10@1+ (0.1,0) [0|102.3] "%"  PC
 SG_ M2P_SOH_B6 : 45|8@1+ (1,0) [0|255] "%"  PC
 SG_ Reserved_25 : 53|11@1+ (1,0) [0|2047] ""  PC

BO_ 2335370922 M2P_SUMDATA43__26: 8 MBMU
 SG_ M2P_SysMinVolt_B6_26 : 0|16@1+ (1,0) [0|65535] "mv"  PC
 SG_ M2P_SysAvgVolt_B6_26 : 16|16@1+ (1,0) [0|65535] "mv"  PC
 SG_ M2P_BMS_Status_B6 : 32|3@1+ (1,0) [0|7] ""  PC
 SG_ M2P_SOC_B6 : 35|10@1+ (0.1,0) [0|102.3] "%"  PC
 SG_ M2P_SOH_B6 : 45|8@1+ (1,0) [0|255] "%"  PC
 SG_ Reserved_26 : 53|11@1+ (1,0) [0|2047] ""  PC

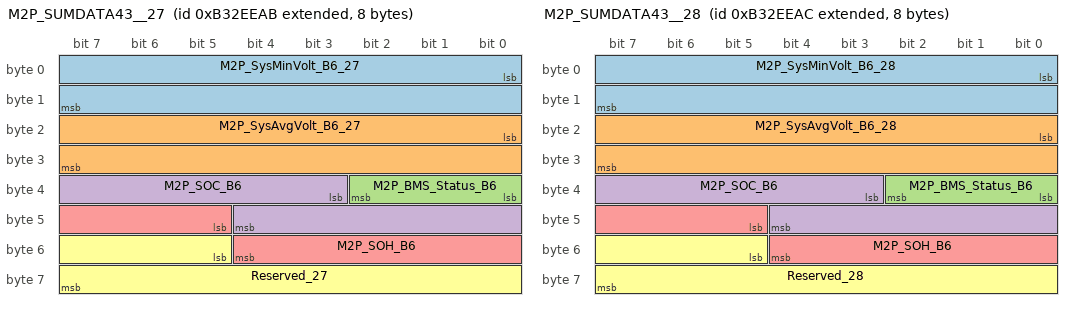
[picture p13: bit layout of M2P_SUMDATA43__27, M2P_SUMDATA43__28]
BO_ 2335370923 M2P_SUMDATA43__27: 8 MBMU
 SG_ M2P_SysMinVolt_B6_27 : 0|16@1+ (1,0) [0|65535] "mv"  PC
 SG_ M2P_SysAvgVolt_B6_27 : 16|16@1+ (1,0) [0|65535] "mv"  PC
 SG_ M2P_BMS_Status_B6 : 32|3@1+ (1,0) [0|7] ""  PC
 SG_ M2P_SOC_B6 : 35|10@1+ (0.1,0) [0|102.3] "%"  PC
 SG_ M2P_SOH_B6 : 45|8@1+ (1,0) [0|255] "%"  PC
 SG_ Reserved_27 : 53|11@1+ (1,0) [0|2047] ""  PC

BO_ 2335370924 M2P_SUMDATA43__28: 8 MBMU
 SG_ M2P_SysMinVolt_B6_28 : 0|16@1+ (1,0) [0|65535] "mv"  PC
 SG_ M2P_SysAvgVolt_B6_28 : 16|16@1+ (1,0) [0|65535] "mv"  PC
 SG_ M2P_BMS_Status_B6 : 32|3@1+ (1,0) [0|7] ""  PC
 SG_ M2P_SOC_B6 : 35|10@1+ (0.1,0) [0|102.3] "%"  PC
 SG_ M2P_SOH_B6 : 45|8@1+ (1,0) [0|255] "%"  PC
 SG_ Reserved_28 : 53|11@1+ (1,0) [0|2047] ""  PC

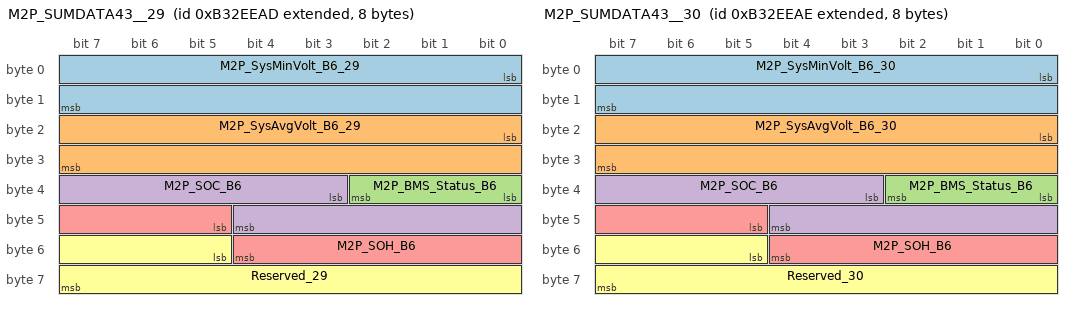
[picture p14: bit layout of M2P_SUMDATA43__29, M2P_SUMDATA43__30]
BO_ 2335370925 M2P_SUMDATA43__29: 8 MBMU
 SG_ M2P_SysMinVolt_B6_29 : 0|16@1+ (1,0) [0|65535] "mv"  PC
 SG_ M2P_SysAvgVolt_B6_29 : 16|16@1+ (1,0) [0|65535] "mv"  PC
 SG_ M2P_BMS_Status_B6 : 32|3@1+ (1,0) [0|7] ""  PC
 SG_ M2P_SOC_B6 : 35|10@1+ (0.1,0) [0|102.3] "%"  PC
 SG_ M2P_SOH_B6 : 45|8@1+ (1,0) [0|255] "%"  PC
 SG_ Reserved_29 : 53|11@1+ (1,0) [0|2047] ""  PC

BO_ 2335370926 M2P_SUMDATA43__30: 8 MBMU
 SG_ M2P_SysMinVolt_B6_30 : 0|16@1+ (1,0) [0|65535] "mv"  PC
 SG_ M2P_SysAvgVolt_B6_30 : 16|16@1+ (1,0) [0|65535] "mv"  PC
 SG_ M2P_BMS_Status_B6 : 32|3@1+ (1,0) [0|7] ""  PC
 SG_ M2P_SOC_B6 : 35|10@1+ (0.1,0) [0|102.3] "%"  PC
 SG_ M2P_SOH_B6 : 45|8@1+ (1,0) [0|255] "%"  PC
 SG_ Reserved_30 : 53|11@1+ (1,0) [0|2047] ""  PC

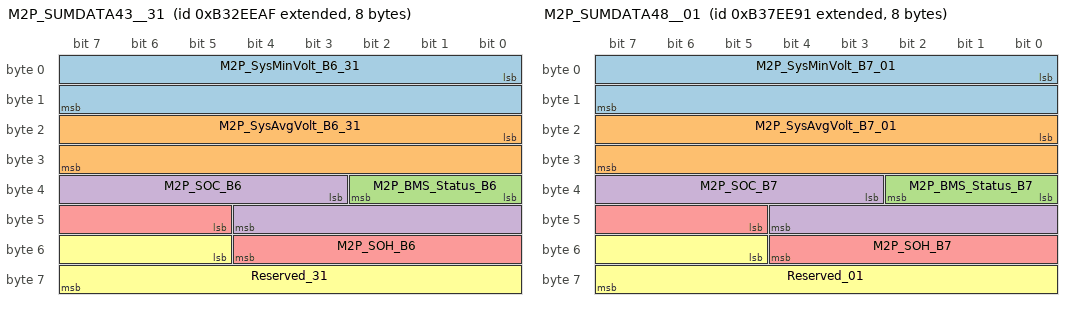
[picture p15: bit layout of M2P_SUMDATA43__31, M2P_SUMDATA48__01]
BO_ 2335370927 M2P_SUMDATA43__31: 8 MBMU
 SG_ M2P_SysMinVolt_B6_31 : 0|16@1+ (1,0) [0|65535] "mv"  PC
 SG_ M2P_SysAvgVolt_B6_31 : 16|16@1+ (1,0) [0|65535] "mv"  PC
 SG_ M2P_BMS_Status_B6 : 32|3@1+ (1,0) [0|7] ""  PC
 SG_ M2P_SOC_B6 : 35|10@1+ (0.1,0) [0|102.3] "%"  PC
 SG_ M2P_SOH_B6 : 45|8@1+ (1,0) [0|255] "%"  PC
 SG_ Reserved_31 : 53|11@1+ (1,0) [0|2047] ""  PC

BO_ 2335436433 M2P_SUMDATA44__01: 8 MBMU
 SG_ M2P_SOE_Charge_B6 : 0|10@1+ (0.1,0) [0|102.3] "%"  PC
 SG_ M2P_SOE_Discharge_B6 : 10|10@1+ (0.1,0) [0|102.3] "%"  PC
 SG_ Reserved_01 : 20|44@1+ (1,0) [0|17592186044415] ""  PC

BO_ 2335436434 M2P_SUMDATA44__02: 8 MBMU
 SG_ M2P_SOE_Charge_B6 : 0|10@1+ (0.1,0) [0|102.3] "%"  PC
 SG_ M2P_SOE_Discharge_B6 : 10|10@1+ (0.1,0) [0|102.3] "%"  PC
 SG_ Reserved_02 : 20|44@1+ (1,0) [0|17592186044415] ""  PC

BO_ 2335436435 M2P_SUMDATA44__03: 8 MBMU
 SG_ M2P_SOE_Charge_B6 : 0|10@1+ (0.1,0) [0|102.3] "%"  PC
 SG_ M2P_SOE_Discharge_B6 : 10|10@1+ (0.1,0) [0|102.3] "%"  PC
 SG_ Reserved_03 : 20|44@1+ (1,0) [0|17592186044415] ""  PC

BO_ 2335436436 M2P_SUMDATA44__04: 8 MBMU
 SG_ M2P_SOE_Charge_B6 : 0|10@1+ (0.1,0) [0|102.3] "%"  PC
 SG_ M2P_SOE_Discharge_B6 : 10|10@1+ (0.1,0) [0|102.3] "%"  PC
 SG_ Reserved_04 : 20|44@1+ (1,0) [0|17592186044415] ""  PC

BO_ 2335436437 M2P_SUMDATA44__05: 8 MBMU
 SG_ M2P_SOE_Charge_B6 : 0|10@1+ (0.1,0) [0|102.3] "%"  PC
 SG_ M2P_SOE_Discharge_B6 : 10|10@1+ (0.1,0) [0|102.3] "%"  PC
 SG_ Reserved_05 : 20|44@1+ (1,0) [0|17592186044415] ""  PC

BO_ 2335436438 M2P_SUMDATA44__06: 8 MBMU
 SG_ M2P_SOE_Charge_B6 : 0|10@1+ (0.1,0) [0|102.3] "%"  PC
 SG_ M2P_SOE_Discharge_B6 : 10|10@1+ (0.1,0) [0|102.3] "%"  PC
 SG_ Reserved_06 : 20|44@1+ (1,0) [0|17592186044415] ""  PC

BO_ 2335436439 M2P_SUMDATA44__07: 8 MBMU
 SG_ M2P_SOE_Charge_B6 : 0|10@1+ (0.1,0) [0|102.3] "%"  PC
 SG_ M2P_SOE_Discharge_B6 : 10|10@1+ (0.1,0) [0|102.3] "%"  PC
 SG_ Reserved_07 : 20|44@1+ (1,0) [0|17592186044415] ""  PC

BO_ 2335436440 M2P_SUMDATA44__08: 8 MBMU
 SG_ M2P_SOE_Charge_B6 : 0|10@1+ (0.1,0) [0|102.3] "%"  PC
 SG_ M2P_SOE_Discharge_B6 : 10|10@1+ (0.1,0) [0|102.3] "%"  PC
 SG_ Reserved_08 : 20|44@1+ (1,0) [0|17592186044415] ""  PC

BO_ 2335436441 M2P_SUMDATA44__09: 8 MBMU
 SG_ M2P_SOE_Charge_B6 : 0|10@1+ (0.1,0) [0|102.3] "%"  PC
 SG_ M2P_SOE_Discharge_B6 : 10|10@1+ (0.1,0) [0|102.3] "%"  PC
 SG_ Reserved_09 : 20|44@1+ (1,0) [0|17592186044415] ""  PC

BO_ 2335436442 M2P_SUMDATA44__10: 8 MBMU
 SG_ M2P_SOE_Charge_B6 : 0|10@1+ (0.1,0) [0|102.3] "%"  PC
 SG_ M2P_SOE_Discharge_B6 : 10|10@1+ (0.1,0) [0|102.3] "%"  PC
 SG_ Reserved_10 : 20|44@1+ (1,0) [0|17592186044415] ""  PC

BO_ 2335436443 M2P_SUMDATA44__11: 8 MBMU
 SG_ M2P_SOE_Charge_B6 : 0|10@1+ (0.1,0) [0|102.3] "%"  PC
 SG_ M2P_SOE_Discharge_B6 : 10|10@1+ (0.1,0) [0|102.3] "%"  PC
 SG_ Reserved_11 : 20|44@1+ (1,0) [0|17592186044415] ""  PC

BO_ 2335436444 M2P_SUMDATA44__12: 8 MBMU
 SG_ M2P_SOE_Charge_B6 : 0|10@1+ (0.1,0) [0|102.3] "%"  PC
 SG_ M2P_SOE_Discharge_B6 : 10|10@1+ (0.1,0) [0|102.3] "%"  PC
 SG_ Reserved_12 : 20|44@1+ (1,0) [0|17592186044415] ""  PC

BO_ 2335436445 M2P_SUMDATA44__13: 8 MBMU
 SG_ M2P_SOE_Charge_B6 : 0|10@1+ (0.1,0) [0|102.3] "%"  PC
 SG_ M2P_SOE_Discharge_B6 : 10|10@1+ (0.1,0) [0|102.3] "%"  PC
 SG_ Reserved_13 : 20|44@1+ (1,0) [0|17592186044415] ""  PC

BO_ 2335436446 M2P_SUMDATA44__14: 8 MBMU
 SG_ M2P_SOE_Charge_B6 : 0|10@1+ (0.1,0) [0|102.3] "%"  PC
 SG_ M2P_SOE_Discharge_B6 : 10|10@1+ (0.1,0) [0|102.3] "%"  PC
 SG_ Reserved_14 : 20|44@1+ (1,0) [0|17592186044415] ""  PC

BO_ 2335436447 M2P_SUMDATA44__15: 8 MBMU
 SG_ M2P_SOE_Charge_B6 : 0|10@1+ (0.1,0) [0|102.3] "%"  PC
 SG_ M2P_SOE_Discharge_B6 : 10|10@1+ (0.1,0) [0|102.3] "%"  PC
 SG_ Reserved_15 : 20|44@1+ (1,0) [0|17592186044415] ""  PC

BO_ 2335436448 M2P_SUMDATA44__16: 8 MBMU
 SG_ M2P_SOE_Charge_B6 : 0|10@1+ (0.1,0) [0|102.3] "%"  PC
 SG_ M2P_SOE_Discharge_B6 : 10|10@1+ (0.1,0) [0|102.3] "%"  PC
 SG_ Reserved_16 : 20|44@1+ (1,0) [0|17592186044415] ""  PC

BO_ 2335436449 M2P_SUMDATA44__17: 8 MBMU
 SG_ M2P_SOE_Charge_B6 : 0|10@1+ (0.1,0) [0|102.3] "%"  PC
 SG_ M2P_SOE_Discharge_B6 : 10|10@1+ (0.1,0) [0|102.3] "%"  PC
 SG_ Reserved_17 : 20|44@1+ (1,0) [0|17592186044415] ""  PC

BO_ 2335436450 M2P_SUMDATA44__18: 8 MBMU
 SG_ M2P_SOE_Charge_B6 : 0|10@1+ (0.1,0) [0|102.3] "%"  PC
 SG_ M2P_SOE_Discharge_B6 : 10|10@1+ (0.1,0) [0|102.3] "%"  PC
 SG_ Reserved_18 : 20|44@1+ (1,0) [0|17592186044415] ""  PC

BO_ 2335436451 M2P_SUMDATA44__19: 8 MBMU
 SG_ M2P_SOE_Charge_B6 : 0|10@1+ (0.1,0) [0|102.3] "%"  PC
 SG_ M2P_SOE_Discharge_B6 : 10|10@1+ (0.1,0) [0|102.3] "%"  PC
 SG_ Reserved_19 : 20|44@1+ (1,0) [0|17592186044415] ""  PC

BO_ 2335436452 M2P_SUMDATA44__20: 8 MBMU
 SG_ M2P_SOE_Charge_B6 : 0|10@1+ (0.1,0) [0|102.3] "%"  PC
 SG_ M2P_SOE_Discharge_B6 : 10|10@1+ (0.1,0) [0|102.3] "%"  PC
 SG_ Reserved_20 : 20|44@1+ (1,0) [0|17592186044415] ""  PC

BO_ 2335436453 M2P_SUMDATA44__21: 8 MBMU
 SG_ M2P_SOE_Charge_B6 : 0|10@1+ (0.1,0) [0|102.3] "%"  PC
 SG_ M2P_SOE_Discharge_B6 : 10|10@1+ (0.1,0) [0|102.3] "%"  PC
 SG_ Reserved_21 : 20|44@1+ (1,0) [0|17592186044415] ""  PC

BO_ 2335436454 M2P_SUMDATA44__22: 8 MBMU
 SG_ M2P_SOE_Charge_B6 : 0|10@1+ (0.1,0) [0|102.3] "%"  PC
 SG_ M2P_SOE_Discharge_B6 : 10|10@1+ (0.1,0) [0|102.3] "%"  PC
 SG_ Reserved_22 : 20|44@1+ (1,0) [0|17592186044415] ""  PC

BO_ 2335436455 M2P_SUMDATA44__23: 8 MBMU
 SG_ M2P_SOE_Charge_B6 : 0|10@1+ (0.1,0) [0|102.3] "%"  PC
 SG_ M2P_SOE_Discharge_B6 : 10|10@1+ (0.1,0) [0|102.3] "%"  PC
 SG_ Reserved_23 : 20|44@1+ (1,0) [0|17592186044415] ""  PC

BO_ 2335436456 M2P_SUMDATA44__24: 8 MBMU
 SG_ M2P_SOE_Charge_B6 : 0|10@1+ (0.1,0) [0|102.3] "%"  PC
 SG_ M2P_SOE_Discharge_B6 : 10|10@1+ (0.1,0) [0|102.3] "%"  PC
 SG_ Reserved_24 : 20|44@1+ (1,0) [0|17592186044415] ""  PC

BO_ 2335436457 M2P_SUMDATA44__25: 8 MBMU
 SG_ M2P_SOE_Charge_B6 : 0|10@1+ (0.1,0) [0|102.3] "%"  PC
 SG_ M2P_SOE_Discharge_B6 : 10|10@1+ (0.1,0) [0|102.3] "%"  PC
 SG_ Reserved_25 : 20|44@1+ (1,0) [0|17592186044415] ""  PC

BO_ 2335436458 M2P_SUMDATA44__26: 8 MBMU
 SG_ M2P_SOE_Charge_B6 : 0|10@1+ (0.1,0) [0|102.3] "%"  PC
 SG_ M2P_SOE_Discharge_B6 : 10|10@1+ (0.1,0) [0|102.3] "%"  PC
 SG_ Reserved_26 : 20|44@1+ (1,0) [0|17592186044415] ""  PC

BO_ 2335436459 M2P_SUMDATA44__27: 8 MBMU
 SG_ M2P_SOE_Charge_B6 : 0|10@1+ (0.1,0) [0|102.3] "%"  PC
 SG_ M2P_SOE_Discharge_B6 : 10|10@1+ (0.1,0) [0|102.3] "%"  PC
 SG_ Reserved_27 : 20|44@1+ (1,0) [0|17592186044415] ""  PC

BO_ 2335436460 M2P_SUMDATA44__28: 8 MBMU
 SG_ M2P_SOE_Charge_B6 : 0|10@1+ (0.1,0) [0|102.3] "%"  PC
 SG_ M2P_SOE_Discharge_B6 : 10|10@1+ (0.1,0) [0|102.3] "%"  PC
 SG_ Reserved_28 : 20|44@1+ (1,0) [0|17592186044415] ""  PC

BO_ 2335436461 M2P_SUMDATA44__29: 8 MBMU
 SG_ M2P_SOE_Charge_B6 : 0|10@1+ (0.1,0) [0|102.3] "%"  PC
 SG_ M2P_SOE_Discharge_B6 : 10|10@1+ (0.1,0) [0|102.3] "%"  PC
 SG_ Reserved_29 : 20|44@1+ (1,0) [0|17592186044415] ""  PC

BO_ 2335436462 M2P_SUMDATA44__30: 8 MBMU
 SG_ M2P_SOE_Charge_B6 : 0|10@1+ (0.1,0) [0|102.3] "%"  PC
 SG_ M2P_SOE_Discharge_B6 : 10|10@1+ (0.1,0) [0|102.3] "%"  PC
 SG_ Reserved_30 : 20|44@1+ (1,0) [0|17592186044415] ""  PC

BO_ 2335436463 M2P_SUMDATA44__31: 8 MBMU
 SG_ M2P_SOE_Charge_B6 : 0|10@1+ (0.1,0) [0|102.3] "%"  PC
 SG_ M2P_SOE_Discharge_B6 : 10|10@1+ (0.1,0) [0|102.3] "%"  PC
 SG_ Reserved_31 : 20|44@1+ (1,0) [0|17592186044415] ""  PC

BO_ 2335501969 M2P_SUMDATA45__01: 8 MBMU
 SG_ M2P_Measure_Vol_B7_01 : 0|16@1+ (0.1,0) [0|6553.5] "V"  PC,SBMU
 SG_ M2P_Current_B7_01 : 16|16@1+ (1,-20000) [-20000|45535] "A"  PC,SBMU
 SG_ M2P_PermitMaxCharge_I_B7_01 : 32|16@1+ (1,-20000) [-20000|45535] "A"  PC
 SG_ M2P_PermitMaxDisCharge_I_B7_01 : 48|16@1+ (1,-20000) [-20000|45535] "A"  PC

BO_ 2335501970 M2P_SUMDATA45__02: 8 MBMU
 SG_ M2P_Measure_Vol_B7_02 : 0|16@1+ (0.1,0) [0|6553.5] "V"  PC,SBMU
 SG_ M2P_Current_B7_02 : 16|16@1+ (1,-20000) [-20000|45535] "A"  PC,SBMU
 SG_ M2P_PermitMaxCharge_I_B7_02 : 32|16@1+ (1,-20000) [-20000|45535] "A"  PC
 SG_ M2P_PermitMaxDisCharge_I_B7_02 : 48|16@1+ (1,-20000) [-20000|45535] "A"  PC

BO_ 2335501971 M2P_SUMDATA45__03: 8 MBMU
 SG_ M2P_Measure_Vol_B7_03 : 0|16@1+ (0.1,0) [0|6553.5] "V"  PC,SBMU
 SG_ M2P_Current_B7_03 : 16|16@1+ (1,-20000) [-20000|45535] "A"  PC,SBMU
 SG_ M2P_PermitMaxCharge_I_B7_03 : 32|16@1+ (1,-20000) [-20000|45535] "A"  PC
 SG_ M2P_PermitMaxDisCharge_I_B7_03 : 48|16@1+ (1,-20000) [-20000|45535] "A"  PC

BO_ 2335501972 M2P_SUMDATA45__04: 8 MBMU
 SG_ M2P_Measure_Vol_B7_04 : 0|16@1+ (0.1,0) [0|6553.5] "V"  PC,SBMU
 SG_ M2P_Current_B7_04 : 16|16@1+ (1,-20000) [-20000|45535] "A"  PC,SBMU
 SG_ M2P_PermitMaxCharge_I_B7_04 : 32|16@1+ (1,-20000) [-20000|45535] "A"  PC
 SG_ M2P_PermitMaxDisCharge_I_B7_04 : 48|16@1+ (1,-20000) [-20000|45535] "A"  PC

BO_ 2335501973 M2P_SUMDATA45__05: 8 MBMU
 SG_ M2P_Measure_Vol_B7_05 : 0|16@1+ (0.1,0) [0|6553.5] "V"  PC,SBMU
 SG_ M2P_Current_B7_05 : 16|16@1+ (1,-20000) [-20000|45535] "A"  PC,SBMU
 SG_ M2P_PermitMaxCharge_I_B7_05 : 32|16@1+ (1,-20000) [-20000|45535] "A"  PC
 SG_ M2P_PermitMaxDisCharge_I_B7_05 : 48|16@1+ (1,-20000) [-20000|45535] "A"  PC

BO_ 2335501974 M2P_SUMDATA45__06: 8 MBMU
 SG_ M2P_Measure_Vol_B7_06 : 0|16@1+ (0.1,0) [0|6553.5] "V"  PC,SBMU
 SG_ M2P_Current_B7_06 : 16|16@1+ (1,-20000) [-20000|45535] "A"  PC,SBMU
 SG_ M2P_PermitMaxCharge_I_B7_06 : 32|16@1+ (1,-20000) [-20000|45535] "A"  PC
 SG_ M2P_PermitMaxDisCharge_I_B7_06 : 48|16@1+ (1,-20000) [-20000|45535] "A"  PC

BO_ 2335501975 M2P_SUMDATA45__07: 8 MBMU
 SG_ M2P_Measure_Vol_B7_07 : 0|16@1+ (0.1,0) [0|6553.5] "V"  PC,SBMU
 SG_ M2P_Current_B7_07 : 16|16@1+ (1,-20000) [-20000|45535] "A"  PC,SBMU
 SG_ M2P_PermitMaxCharge_I_B7_07 : 32|16@1+ (1,-20000) [-20000|45535] "A"  PC
 SG_ M2P_PermitMaxDisCharge_I_B7_07 : 48|16@1+ (1,-20000) [-20000|45535] "A"  PC

BO_ 2335501976 M2P_SUMDATA45__08: 8 MBMU
 SG_ M2P_Measure_Vol_B7_08 : 0|16@1+ (0.1,0) [0|6553.5] "V"  PC,SBMU
 SG_ M2P_Current_B7_08 : 16|16@1+ (1,-20000) [-20000|45535] "A"  PC,SBMU
 SG_ M2P_PermitMaxCharge_I_B7_08 : 32|16@1+ (1,-20000) [-20000|45535] "A"  PC
 SG_ M2P_PermitMaxDisCharge_I_B7_08 : 48|16@1+ (1,-20000) [-20000|45535] "A"  PC

BO_ 2335501977 M2P_SUMDATA45__09: 8 MBMU
 SG_ M2P_Measure_Vol_B7_09 : 0|16@1+ (0.1,0) [0|6553.5] "V"  PC,SBMU
 SG_ M2P_Current_B7_09 : 16|16@1+ (1,-20000) [-20000|45535] "A"  PC,SBMU
 SG_ M2P_PermitMaxCharge_I_B7_09 : 32|16@1+ (1,-20000) [-20000|45535] "A"  PC
 SG_ M2P_PermitMaxDisCharge_I_B7_09 : 48|16@1+ (1,-20000) [-20000|45535] "A"  PC

BO_ 2335501978 M2P_SUMDATA45__10: 8 MBMU
 SG_ M2P_Measure_Vol_B7_10 : 0|16@1+ (0.1,0) [0|6553.5] "V"  PC,SBMU
 SG_ M2P_Current_B7_10 : 16|16@1+ (1,-20000) [-20000|45535] "A"  PC,SBMU
 SG_ M2P_PermitMaxCharge_I_B7_10 : 32|16@1+ (1,-20000) [-20000|45535] "A"  PC
 SG_ M2P_PermitMaxDisCharge_I_B7_10 : 48|16@1+ (1,-20000) [-20000|45535] "A"  PC

BO_ 2335501979 M2P_SUMDATA45__11: 8 MBMU
 SG_ M2P_Measure_Vol_B7_11 : 0|16@1+ (0.1,0) [0|6553.5] "V"  PC,SBMU
 SG_ M2P_Current_B7_11 : 16|16@1+ (1,-20000) [-20000|45535] "A"  PC,SBMU
 SG_ M2P_PermitMaxCharge_I_B7_11 : 32|16@1+ (1,-20000) [-20000|45535] "A"  PC
 SG_ M2P_PermitMaxDisCharge_I_B7_11 : 48|16@1+ (1,-20000) [-20000|45535] "A"  PC

BO_ 2335501980 M2P_SUMDATA45__12: 8 MBMU
 SG_ M2P_Measure_Vol_B7_12 : 0|16@1+ (0.1,0) [0|6553.5] "V"  PC,SBMU
 SG_ M2P_Current_B7_12 : 16|16@1+ (1,-20000) [-20000|45535] "A"  PC,SBMU
 SG_ M2P_PermitMaxCharge_I_B7_12 : 32|16@1+ (1,-20000) [-20000|45535] "A"  PC
 SG_ M2P_PermitMaxDisCharge_I_B7_12 : 48|16@1+ (1,-20000) [-20000|45535] "A"  PC

BO_ 2335501981 M2P_SUMDATA45__13: 8 MBMU
 SG_ M2P_Measure_Vol_B7_13 : 0|16@1+ (0.1,0) [0|6553.5] "V"  PC,SBMU
 SG_ M2P_Current_B7_13 : 16|16@1+ (1,-20000) [-20000|45535] "A"  PC,SBMU
 SG_ M2P_PermitMaxCharge_I_B7_13 : 32|16@1+ (1,-20000) [-20000|45535] "A"  PC
 SG_ M2P_PermitMaxDisCharge_I_B7_13 : 48|16@1+ (1,-20000) [-20000|45535] "A"  PC

BO_ 2335501982 M2P_SUMDATA45__14: 8 MBMU
 SG_ M2P_Measure_Vol_B7_14 : 0|16@1+ (0.1,0) [0|6553.5] "V"  PC,SBMU
 SG_ M2P_Current_B7_14 : 16|16@1+ (1,-20000) [-20000|45535] "A"  PC,SBMU
 SG_ M2P_PermitMaxCharge_I_B7_14 : 32|16@1+ (1,-20000) [-20000|45535] "A"  PC
 SG_ M2P_PermitMaxDisCharge_I_B7_14 : 48|16@1+ (1,-20000) [-20000|45535] "A"  PC

BO_ 2335501983 M2P_SUMDATA45__15: 8 MBMU
 SG_ M2P_Measure_Vol_B7_15 : 0|16@1+ (0.1,0) [0|6553.5] "V"  PC,SBMU
 SG_ M2P_Current_B7_15 : 16|16@1+ (1,-20000) [-20000|45535] "A"  PC,SBMU
 SG_ M2P_PermitMaxCharge_I_B7_15 : 32|16@1+ (1,-20000) [-20000|45535] "A"  PC
 SG_ M2P_PermitMaxDisCharge_I_B7_15 : 48|16@1+ (1,-20000) [-20000|45535] "A"  PC

BO_ 2335501984 M2P_SUMDATA45__16: 8 MBMU
 SG_ M2P_Measure_Vol_B7_16 : 0|16@1+ (0.1,0) [0|6553.5] "V"  PC,SBMU
 SG_ M2P_Current_B7_16 : 16|16@1+ (1,-20000) [-20000|45535] "A"  PC,SBMU
 SG_ M2P_PermitMaxCharge_I_B7_16 : 32|16@1+ (1,-20000) [-20000|45535] "A"  PC
 SG_ M2P_PermitMaxDisCharge_I_B7_16 : 48|16@1+ (1,-20000) [-20000|45535] "A"  PC

BO_ 2335501985 M2P_SUMDATA45__17: 8 MBMU
 SG_ M2P_Measure_Vol_B7_17 : 0|16@1+ (0.1,0) [0|6553.5] "V"  PC,SBMU
 SG_ M2P_Current_B7_17 : 16|16@1+ (1,-20000) [-20000|45535] "A"  PC,SBMU
 SG_ M2P_PermitMaxCharge_I_B7_17 : 32|16@1+ (1,-20000) [-20000|45535] "A"  PC
 SG_ M2P_PermitMaxDisCharge_I_B7_17 : 48|16@1+ (1,-20000) [-20000|45535] "A"  PC

BO_ 2335501986 M2P_SUMDATA45__18: 8 MBMU
 SG_ M2P_Measure_Vol_B7_18 : 0|16@1+ (0.1,0) [0|6553.5] "V"  PC,SBMU
 SG_ M2P_Current_B7_18 : 16|16@1+ (1,-20000) [-20000|45535] "A"  PC,SBMU
 SG_ M2P_PermitMaxCharge_I_B7_18 : 32|16@1+ (1,-20000) [-20000|45535] "A"  PC
 SG_ M2P_PermitMaxDisCharge_I_B7_18 : 48|16@1+ (1,-20000) [-20000|45535] "A"  PC

BO_ 2335501987 M2P_SUMDATA45__19: 8 MBMU
 SG_ M2P_Measure_Vol_B7_19 : 0|16@1+ (0.1,0) [0|6553.5] "V"  PC,SBMU
 SG_ M2P_Current_B7_19 : 16|16@1+ (1,-20000) [-20000|45535] "A"  PC,SBMU
 SG_ M2P_PermitMaxCharge_I_B7_19 : 32|16@1+ (1,-20000) [-20000|45535] "A"  PC
 SG_ M2P_PermitMaxDisCharge_I_B7_19 : 48|16@1+ (1,-20000) [-20000|45535] "A"  PC

BO_ 2335501988 M2P_SUMDATA45__20: 8 MBMU
 SG_ M2P_Measure_Vol_B7_20 : 0|16@1+ (0.1,0) [0|6553.5] "V"  PC,SBMU
 SG_ M2P_Current_B7_20 : 16|16@1+ (1,-20000) [-20000|45535] "A"  PC,SBMU
 SG_ M2P_PermitMaxCharge_I_B7_20 : 32|16@1+ (1,-20000) [-20000|45535] "A"  PC
 SG_ M2P_PermitMaxDisCharge_I_B7_20 : 48|16@1+ (1,-20000) [-20000|45535] "A"  PC

BO_ 2335501989 M2P_SUMDATA45__21: 8 MBMU
 SG_ M2P_Measure_Vol_B7_21 : 0|16@1+ (0.1,0) [0|6553.5] "V"  PC,SBMU
 SG_ M2P_Current_B7_21 : 16|16@1+ (1,-20000) [-20000|45535] "A"  PC,SBMU
 SG_ M2P_PermitMaxCharge_I_B7_21 : 32|16@1+ (1,-20000) [-20000|45535] "A"  PC
 SG_ M2P_PermitMaxDisCharge_I_B7_21 : 48|16@1+ (1,-20000) [-20000|45535] "A"  PC

BO_ 2335501990 M2P_SUMDATA45__22: 8 MBMU
 SG_ M2P_Measure_Vol_B7_22 : 0|16@1+ (0.1,0) [0|6553.5] "V"  PC,SBMU
 SG_ M2P_Current_B7_22 : 16|16@1+ (1,-20000) [-20000|45535] "A"  PC,SBMU
 SG_ M2P_PermitMaxCharge_I_B7_22 : 32|16@1+ (1,-20000) [-20000|45535] "A"  PC
 SG_ M2P_PermitMaxDisCharge_I_B7_22 : 48|16@1+ (1,-20000) [-20000|45535] "A"  PC

BO_ 2335501991 M2P_SUMDATA45__23: 8 MBMU
 SG_ M2P_Measure_Vol_B7_23 : 0|16@1+ (0.1,0) [0|6553.5] "V"  PC,SBMU
 SG_ M2P_Current_B7_23 : 16|16@1+ (1,-20000) [-20000|45535] "A"  PC,SBMU
 SG_ M2P_PermitMaxCharge_I_B7_23 : 32|16@1+ (1,-20000) [-20000|45535] "A"  PC
 SG_ M2P_PermitMaxDisCharge_I_B7_23 : 48|16@1+ (1,-20000) [-20000|45535] "A"  PC

BO_ 2335501992 M2P_SUMDATA45__24: 8 MBMU
 SG_ M2P_Measure_Vol_B7_24 : 0|16@1+ (0.1,0) [0|6553.5] "V"  PC,SBMU
 SG_ M2P_Current_B7_24 : 16|16@1+ (1,-20000) [-20000|45535] "A"  PC,SBMU
 SG_ M2P_PermitMaxCharge_I_B7_24 : 32|16@1+ (1,-20000) [-20000|45535] "A"  PC
 SG_ M2P_PermitMaxDisCharge_I_B7_24 : 48|16@1+ (1,-20000) [-20000|45535] "A"  PC

BO_ 2335501993 M2P_SUMDATA45__25: 8 MBMU
 SG_ M2P_Measure_Vol_B7_25 : 0|16@1+ (0.1,0) [0|6553.5] "V"  PC,SBMU
 SG_ M2P_Current_B7_25 : 16|16@1+ (1,-20000) [-20000|45535] "A"  PC,SBMU
 SG_ M2P_PermitMaxCharge_I_B7_25 : 32|16@1+ (1,-20000) [-20000|45535] "A"  PC
 SG_ M2P_PermitMaxDisCharge_I_B7_25 : 48|16@1+ (1,-20000) [-20000|45535] "A"  PC

BO_ 2335501994 M2P_SUMDATA45__26: 8 MBMU
 SG_ M2P_Measure_Vol_B7_26 : 0|16@1+ (0.1,0) [0|6553.5] "V"  PC,SBMU
 SG_ M2P_Current_B7_26 : 16|16@1+ (1,-20000) [-20000|45535] "A"  PC,SBMU
 SG_ M2P_PermitMaxCharge_I_B7_26 : 32|16@1+ (1,-20000) [-20000|45535] "A"  PC
 SG_ M2P_PermitMaxDisCharge_I_B7_26 : 48|16@1+ (1,-20000) [-20000|45535] "A"  PC

BO_ 2335501995 M2P_SUMDATA45__27: 8 MBMU
 SG_ M2P_Measure_Vol_B7_27 : 0|16@1+ (0.1,0) [0|6553.5] "V"  PC,SBMU
 SG_ M2P_Current_B7_27 : 16|16@1+ (1,-20000) [-20000|45535] "A"  PC,SBMU
 SG_ M2P_PermitMaxCharge_I_B7_27 : 32|16@1+ (1,-20000) [-20000|45535] "A"  PC
 SG_ M2P_PermitMaxDisCharge_I_B7_27 : 48|16@1+ (1,-20000) [-20000|45535] "A"  PC

BO_ 2335501996 M2P_SUMDATA45__28: 8 MBMU
 SG_ M2P_Measure_Vol_B7_28 : 0|16@1+ (0.1,0) [0|6553.5] "V"  PC,SBMU
 SG_ M2P_Current_B7_28 : 16|16@1+ (1,-20000) [-20000|45535] "A"  PC,SBMU
 SG_ M2P_PermitMaxCharge_I_B7_28 : 32|16@1+ (1,-20000) [-20000|45535] "A"  PC
 SG_ M2P_PermitMaxDisCharge_I_B7_28 : 48|16@1+ (1,-20000) [-20000|45535] "A"  PC

BO_ 2335501997 M2P_SUMDATA45__29: 8 MBMU
 SG_ M2P_Measure_Vol_B7_29 : 0|16@1+ (0.1,0) [0|6553.5] "V"  PC,SBMU
 SG_ M2P_Current_B7_29 : 16|16@1+ (1,-20000) [-20000|45535] "A"  PC,SBMU
 SG_ M2P_PermitMaxCharge_I_B7_29 : 32|16@1+ (1,-20000) [-20000|45535] "A"  PC
 SG_ M2P_PermitMaxDisCharge_I_B7_29 : 48|16@1+ (1,-20000) [-20000|45535] "A"  PC

BO_ 2335501998 M2P_SUMDATA45__30: 8 MBMU
 SG_ M2P_Measure_Vol_B7_30 : 0|16@1+ (0.1,0) [0|6553.5] "V"  PC,SBMU
 SG_ M2P_Current_B7_30 : 16|16@1+ (1,-20000) [-20000|45535] "A"  PC,SBMU
 SG_ M2P_PermitMaxCharge_I_B7_30 : 32|16@1+ (1,-20000) [-20000|45535] "A"  PC
 SG_ M2P_PermitMaxDisCharge_I_B7_30 : 48|16@1+ (1,-20000) [-20000|45535] "A"  PC

BO_ 2335501999 M2P_SUMDATA45__31: 8 MBMU
 SG_ M2P_Measure_Vol_B7_31 : 0|16@1+ (0.1,0) [0|6553.5] "V"  PC,SBMU
 SG_ M2P_Current_B7_31 : 16|16@1+ (1,-20000) [-20000|45535] "A"  PC,SBMU
 SG_ M2P_PermitMaxCharge_I_B7_31 : 32|16@1+ (1,-20000) [-20000|45535] "A"  PC
 SG_ M2P_PermitMaxDisCharge_I_B7_31 : 48|16@1+ (1,-20000) [-20000|45535] "A"  PC

BO_ 2335567505 M2P_SUMDATA46__01: 8 MBMU
 SG_ M2P_PermitMaxVolt_B7_01 : 0|16@1+ (0.1,0) [0|6553.5] "V"  PC
 SG_ M2P_PermitMinVolt_B7_01 : 16|16@1+ (0.1,0) [0|6553.5] "V"  PC
 SG_ M2P_PermitMaxPow_Chg_B7_01 : 32|16@1+ (1,-20000) [-20000|45535] "Kw"  PC
 SG_ M2P_PermitMaxPow_DisChg_B7_01 : 48|16@1+ (1,-20000) [-20000|45535] "Kw"  PC

BO_ 2335567506 M2P_SUMDATA46__02: 8 MBMU
 SG_ M2P_PermitMaxVolt_B7_02 : 0|16@1+ (0.1,0) [0|6553.5] "V"  PC
 SG_ M2P_PermitMinVolt_B7_02 : 16|16@1+ (0.1,0) [0|6553.5] "V"  PC
 SG_ M2P_PermitMaxPow_Chg_B7_02 : 32|16@1+ (1,-20000) [-20000|45535] "Kw"  PC
 SG_ M2P_PermitMaxPow_DisChg_B7_02 : 48|16@1+ (1,-20000) [-20000|45535] "Kw"  PC

BO_ 2335567507 M2P_SUMDATA46__03: 8 MBMU
 SG_ M2P_PermitMaxVolt_B7_03 : 0|16@1+ (0.1,0) [0|6553.5] "V"  PC
 SG_ M2P_PermitMinVolt_B7_03 : 16|16@1+ (0.1,0) [0|6553.5] "V"  PC
 SG_ M2P_PermitMaxPow_Chg_B7_03 : 32|16@1+ (1,-20000) [-20000|45535] "Kw"  PC
 SG_ M2P_PermitMaxPow_DisChg_B7_03 : 48|16@1+ (1,-20000) [-20000|45535] "Kw"  PC

BO_ 2335567508 M2P_SUMDATA46__04: 8 MBMU
 SG_ M2P_PermitMaxVolt_B7_04 : 0|16@1+ (0.1,0) [0|6553.5] "V"  PC
 SG_ M2P_PermitMinVolt_B7_04 : 16|16@1+ (0.1,0) [0|6553.5] "V"  PC
 SG_ M2P_PermitMaxPow_Chg_B7_04 : 32|16@1+ (1,-20000) [-20000|45535] "Kw"  PC
 SG_ M2P_PermitMaxPow_DisChg_B7_04 : 48|16@1+ (1,-20000) [-20000|45535] "Kw"  PC

BO_ 2335567509 M2P_SUMDATA46__05: 8 MBMU
 SG_ M2P_PermitMaxVolt_B7_05 : 0|16@1+ (0.1,0) [0|6553.5] "V"  PC
 SG_ M2P_PermitMinVolt_B7_05 : 16|16@1+ (0.1,0) [0|6553.5] "V"  PC
 SG_ M2P_PermitMaxPow_Chg_B7_05 : 32|16@1+ (1,-20000) [-20000|45535] "Kw"  PC
 SG_ M2P_PermitMaxPow_DisChg_B7_05 : 48|16@1+ (1,-20000) [-20000|45535] "Kw"  PC

BO_ 2335567510 M2P_SUMDATA46__06: 8 MBMU
 SG_ M2P_PermitMaxVolt_B7_06 : 0|16@1+ (0.1,0) [0|6553.5] "V"  PC
 SG_ M2P_PermitMinVolt_B7_06 : 16|16@1+ (0.1,0) [0|6553.5] "V"  PC
 SG_ M2P_PermitMaxPow_Chg_B7_06 : 32|16@1+ (1,-20000) [-20000|45535] "Kw"  PC
 SG_ M2P_PermitMaxPow_DisChg_B7_06 : 48|16@1+ (1,-20000) [-20000|45535] "Kw"  PC

BO_ 2335567511 M2P_SUMDATA46__07: 8 MBMU
 SG_ M2P_PermitMaxVolt_B7_07 : 0|16@1+ (0.1,0) [0|6553.5] "V"  PC
 SG_ M2P_PermitMinVolt_B7_07 : 16|16@1+ (0.1,0) [0|6553.5] "V"  PC
 SG_ M2P_PermitMaxPow_Chg_B7_07 : 32|16@1+ (1,-20000) [-20000|45535] "Kw"  PC
 SG_ M2P_PermitMaxPow_DisChg_B7_07 : 48|16@1+ (1,-20000) [-20000|45535] "Kw"  PC

BO_ 2335567512 M2P_SUMDATA46__08: 8 MBMU
 SG_ M2P_PermitMaxVolt_B7_08 : 0|16@1+ (0.1,0) [0|6553.5] "V"  PC
 SG_ M2P_PermitMinVolt_B7_08 : 16|16@1+ (0.1,0) [0|6553.5] "V"  PC
 SG_ M2P_PermitMaxPow_Chg_B7_08 : 32|16@1+ (1,-20000) [-20000|45535] "Kw"  PC
 SG_ M2P_PermitMaxPow_DisChg_B7_08 : 48|16@1+ (1,-20000) [-20000|45535] "Kw"  PC

BO_ 2335567513 M2P_SUMDATA46__09: 8 MBMU
 SG_ M2P_PermitMaxVolt_B7_09 : 0|16@1+ (0.1,0) [0|6553.5] "V"  PC
 SG_ M2P_PermitMinVolt_B7_09 : 16|16@1+ (0.1,0) [0|6553.5] "V"  PC
 SG_ M2P_PermitMaxPow_Chg_B7_09 : 32|16@1+ (1,-20000) [-20000|45535] "Kw"  PC
 SG_ M2P_PermitMaxPow_DisChg_B7_09 : 48|16@1+ (1,-20000) [-20000|45535] "Kw"  PC

BO_ 2335567514 M2P_SUMDATA46__10: 8 MBMU
 SG_ M2P_PermitMaxVolt_B7_10 : 0|16@1+ (0.1,0) [0|6553.5] "V"  PC
 SG_ M2P_PermitMinVolt_B7_10 : 16|16@1+ (0.1,0) [0|6553.5] "V"  PC
 SG_ M2P_PermitMaxPow_Chg_B7_10 : 32|16@1+ (1,-20000) [-20000|45535] "Kw"  PC
 SG_ M2P_PermitMaxPow_DisChg_B7_10 : 48|16@1+ (1,-20000) [-20000|45535] "Kw"  PC

BO_ 2335567515 M2P_SUMDATA46__11: 8 MBMU
 SG_ M2P_PermitMaxVolt_B7_11 : 0|16@1+ (0.1,0) [0|6553.5] "V"  PC
 SG_ M2P_PermitMinVolt_B7_11 : 16|16@1+ (0.1,0) [0|6553.5] "V"  PC
 SG_ M2P_PermitMaxPow_Chg_B7_11 : 32|16@1+ (1,-20000) [-20000|45535] "Kw"  PC
 SG_ M2P_PermitMaxPow_DisChg_B7_11 : 48|16@1+ (1,-20000) [-20000|45535] "Kw"  PC

BO_ 2335567516 M2P_SUMDATA46__12: 8 MBMU
 SG_ M2P_PermitMaxVolt_B7_12 : 0|16@1+ (0.1,0) [0|6553.5] "V"  PC
 SG_ M2P_PermitMinVolt_B7_12 : 16|16@1+ (0.1,0) [0|6553.5] "V"  PC
 SG_ M2P_PermitMaxPow_Chg_B7_12 : 32|16@1+ (1,-20000) [-20000|45535] "Kw"  PC
 SG_ M2P_PermitMaxPow_DisChg_B7_12 : 48|16@1+ (1,-20000) [-20000|45535] "Kw"  PC

BO_ 2335567517 M2P_SUMDATA46__13: 8 MBMU
 SG_ M2P_PermitMaxVolt_B7_13 : 0|16@1+ (0.1,0) [0|6553.5] "V"  PC
 SG_ M2P_PermitMinVolt_B7_13 : 16|16@1+ (0.1,0) [0|6553.5] "V"  PC
 SG_ M2P_PermitMaxPow_Chg_B7_13 : 32|16@1+ (1,-20000) [-20000|45535] "Kw"  PC
 SG_ M2P_PermitMaxPow_DisChg_B7_13 : 48|16@1+ (1,-20000) [-20000|45535] "Kw"  PC

BO_ 2335567518 M2P_SUMDATA46__14: 8 MBMU
 SG_ M2P_PermitMaxVolt_B7_14 : 0|16@1+ (0.1,0) [0|6553.5] "V"  PC
 SG_ M2P_PermitMinVolt_B7_14 : 16|16@1+ (0.1,0) [0|6553.5] "V"  PC
 SG_ M2P_PermitMaxPow_Chg_B7_14 : 32|16@1+ (1,-20000) [-20000|45535] "Kw"  PC
 SG_ M2P_PermitMaxPow_DisChg_B7_14 : 48|16@1+ (1,-20000) [-20000|45535] "Kw"  PC

BO_ 2335567519 M2P_SUMDATA46__15: 8 MBMU
 SG_ M2P_PermitMaxVolt_B7_15 : 0|16@1+ (0.1,0) [0|6553.5] "V"  PC
 SG_ M2P_PermitMinVolt_B7_15 : 16|16@1+ (0.1,0) [0|6553.5] "V"  PC
 SG_ M2P_PermitMaxPow_Chg_B7_15 : 32|16@1+ (1,-20000) [-20000|45535] "Kw"  PC
 SG_ M2P_PermitMaxPow_DisChg_B7_15 : 48|16@1+ (1,-20000) [-20000|45535] "Kw"  PC

BO_ 2335567520 M2P_SUMDATA46__16: 8 MBMU
 SG_ M2P_PermitMaxVolt_B7_16 : 0|16@1+ (0.1,0) [0|6553.5] "V"  PC
 SG_ M2P_PermitMinVolt_B7_16 : 16|16@1+ (0.1,0) [0|6553.5] "V"  PC
 SG_ M2P_PermitMaxPow_Chg_B7_16 : 32|16@1+ (1,-20000) [-20000|45535] "Kw"  PC
 SG_ M2P_PermitMaxPow_DisChg_B7_16 : 48|16@1+ (1,-20000) [-20000|45535] "Kw"  PC

BO_ 2335567521 M2P_SUMDATA46__17: 8 MBMU
 SG_ M2P_PermitMaxVolt_B7_17 : 0|16@1+ (0.1,0) [0|6553.5] "V"  PC
 SG_ M2P_PermitMinVolt_B7_17 : 16|16@1+ (0.1,0) [0|6553.5] "V"  PC
 SG_ M2P_PermitMaxPow_Chg_B7_17 : 32|16@1+ (1,-20000) [-20000|45535] "Kw"  PC
 SG_ M2P_PermitMaxPow_DisChg_B7_17 : 48|16@1+ (1,-20000) [-20000|45535] "Kw"  PC

BO_ 2335567522 M2P_SUMDATA46__18: 8 MBMU
 SG_ M2P_PermitMaxVolt_B7_18 : 0|16@1+ (0.1,0) [0|6553.5] "V"  PC
 SG_ M2P_PermitMinVolt_B7_18 : 16|16@1+ (0.1,0) [0|6553.5] "V"  PC
 SG_ M2P_PermitMaxPow_Chg_B7_18 : 32|16@1+ (1,-20000) [-20000|45535] "Kw"  PC
 SG_ M2P_PermitMaxPow_DisChg_B7_18 : 48|16@1+ (1,-20000) [-20000|45535] "Kw"  PC

BO_ 2335567523 M2P_SUMDATA46__19: 8 MBMU
 SG_ M2P_PermitMaxVolt_B7_19 : 0|16@1+ (0.1,0) [0|6553.5] "V"  PC
 SG_ M2P_PermitMinVolt_B7_19 : 16|16@1+ (0.1,0) [0|6553.5] "V"  PC
 SG_ M2P_PermitMaxPow_Chg_B7_19 : 32|16@1+ (1,-20000) [-20000|45535] "Kw"  PC
 SG_ M2P_PermitMaxPow_DisChg_B7_19 : 48|16@1+ (1,-20000) [-20000|45535] "Kw"  PC

BO_ 2335567524 M2P_SUMDATA46__20: 8 MBMU
 SG_ M2P_PermitMaxVolt_B7_20 : 0|16@1+ (0.1,0) [0|6553.5] "V"  PC
 SG_ M2P_PermitMinVolt_B7_20 : 16|16@1+ (0.1,0) [0|6553.5] "V"  PC
 SG_ M2P_PermitMaxPow_Chg_B7_20 : 32|16@1+ (1,-20000) [-20000|45535] "Kw"  PC
 SG_ M2P_PermitMaxPow_DisChg_B7_20 : 48|16@1+ (1,-20000) [-20000|45535] "Kw"  PC

BO_ 2335567525 M2P_SUMDATA46__21: 8 MBMU
 SG_ M2P_PermitMaxVolt_B7_21 : 0|16@1+ (0.1,0) [0|6553.5] "V"  PC
 SG_ M2P_PermitMinVolt_B7_21 : 16|16@1+ (0.1,0) [0|6553.5] "V"  PC
 SG_ M2P_PermitMaxPow_Chg_B7_21 : 32|16@1+ (1,-20000) [-20000|45535] "Kw"  PC
 SG_ M2P_PermitMaxPow_DisChg_B7_21 : 48|16@1+ (1,-20000) [-20000|45535] "Kw"  PC

BO_ 2335567526 M2P_SUMDATA46__22: 8 MBMU
 SG_ M2P_PermitMaxVolt_B7_22 : 0|16@1+ (0.1,0) [0|6553.5] "V"  PC
 SG_ M2P_PermitMinVolt_B7_22 : 16|16@1+ (0.1,0) [0|6553.5] "V"  PC
 SG_ M2P_PermitMaxPow_Chg_B7_22 : 32|16@1+ (1,-20000) [-20000|45535] "Kw"  PC
 SG_ M2P_PermitMaxPow_DisChg_B7_22 : 48|16@1+ (1,-20000) [-20000|45535] "Kw"  PC

BO_ 2335567527 M2P_SUMDATA46__23: 8 MBMU
 SG_ M2P_PermitMaxVolt_B7_23 : 0|16@1+ (0.1,0) [0|6553.5] "V"  PC
 SG_ M2P_PermitMinVolt_B7_23 : 16|16@1+ (0.1,0) [0|6553.5] "V"  PC
 SG_ M2P_PermitMaxPow_Chg_B7_23 : 32|16@1+ (1,-20000) [-20000|45535] "Kw"  PC
 SG_ M2P_PermitMaxPow_DisChg_B7_23 : 48|16@1+ (1,-20000) [-20000|45535] "Kw"  PC

BO_ 2335567528 M2P_SUMDATA46__24: 8 MBMU
 SG_ M2P_PermitMaxVolt_B7_24 : 0|16@1+ (0.1,0) [0|6553.5] "V"  PC
 SG_ M2P_PermitMinVolt_B7_24 : 16|16@1+ (0.1,0) [0|6553.5] "V"  PC
 SG_ M2P_PermitMaxPow_Chg_B7_24 : 32|16@1+ (1,-20000) [-20000|45535] "Kw"  PC
 SG_ M2P_PermitMaxPow_DisChg_B7_24 : 48|16@1+ (1,-20000) [-20000|45535] "Kw"  PC

BO_ 2335567529 M2P_SUMDATA46__25: 8 MBMU
 SG_ M2P_PermitMaxVolt_B7_25 : 0|16@1+ (0.1,0) [0|6553.5] "V"  PC
 SG_ M2P_PermitMinVolt_B7_25 : 16|16@1+ (0.1,0) [0|6553.5] "V"  PC
 SG_ M2P_PermitMaxPow_Chg_B7_25 : 32|16@1+ (1,-20000) [-20000|45535] "Kw"  PC
 SG_ M2P_PermitMaxPow_DisChg_B7_25 : 48|16@1+ (1,-20000) [-20000|45535] "Kw"  PC

BO_ 2335567530 M2P_SUMDATA46__26: 8 MBMU
 SG_ M2P_PermitMaxVolt_B7_26 : 0|16@1+ (0.1,0) [0|6553.5] "V"  PC
 SG_ M2P_PermitMinVolt_B7_26 : 16|16@1+ (0.1,0) [0|6553.5] "V"  PC
 SG_ M2P_PermitMaxPow_Chg_B7_26 : 32|16@1+ (1,-20000) [-20000|45535] "Kw"  PC
 SG_ M2P_PermitMaxPow_DisChg_B7_26 : 48|16@1+ (1,-20000) [-20000|45535] "Kw"  PC

BO_ 2335567531 M2P_SUMDATA46__27: 8 MBMU
 SG_ M2P_PermitMaxVolt_B7_27 : 0|16@1+ (0.1,0) [0|6553.5] "V"  PC
 SG_ M2P_PermitMinVolt_B7_27 : 16|16@1+ (0.1,0) [0|6553.5] "V"  PC
 SG_ M2P_PermitMaxPow_Chg_B7_27 : 32|16@1+ (1,-20000) [-20000|45535] "Kw"  PC
 SG_ M2P_PermitMaxPow_DisChg_B7_27 : 48|16@1+ (1,-20000) [-20000|45535] "Kw"  PC

BO_ 2335567532 M2P_SUMDATA46__28: 8 MBMU
 SG_ M2P_PermitMaxVolt_B7_28 : 0|16@1+ (0.1,0) [0|6553.5] "V"  PC
 SG_ M2P_PermitMinVolt_B7_28 : 16|16@1+ (0.1,0) [0|6553.5] "V"  PC
 SG_ M2P_PermitMaxPow_Chg_B7_28 : 32|16@1+ (1,-20000) [-20000|45535] "Kw"  PC
 SG_ M2P_PermitMaxPow_DisChg_B7_28 : 48|16@1+ (1,-20000) [-20000|45535] "Kw"  PC

BO_ 2335567533 M2P_SUMDATA46__29: 8 MBMU
 SG_ M2P_PermitMaxVolt_B7_29 : 0|16@1+ (0.1,0) [0|6553.5] "V"  PC
 SG_ M2P_PermitMinVolt_B7_29 : 16|16@1+ (0.1,0) [0|6553.5] "V"  PC
 SG_ M2P_PermitMaxPow_Chg_B7_29 : 32|16@1+ (1,-20000) [-20000|45535] "Kw"  PC
 SG_ M2P_PermitMaxPow_DisChg_B7_29 : 48|16@1+ (1,-20000) [-20000|45535] "Kw"  PC

BO_ 2335567534 M2P_SUMDATA46__30: 8 MBMU
 SG_ M2P_PermitMaxVolt_B7_30 : 0|16@1+ (0.1,0) [0|6553.5] "V"  PC
 SG_ M2P_PermitMinVolt_B7_30 : 16|16@1+ (0.1,0) [0|6553.5] "V"  PC
 SG_ M2P_PermitMaxPow_Chg_B7_30 : 32|16@1+ (1,-20000) [-20000|45535] "Kw"  PC
 SG_ M2P_PermitMaxPow_DisChg_B7_30 : 48|16@1+ (1,-20000) [-20000|45535] "Kw"  PC

BO_ 2335567535 M2P_SUMDATA46__31: 8 MBMU
 SG_ M2P_PermitMaxVolt_B7_31 : 0|16@1+ (0.1,0) [0|6553.5] "V"  PC
 SG_ M2P_PermitMinVolt_B7_31 : 16|16@1+ (0.1,0) [0|6553.5] "V"  PC
 SG_ M2P_PermitMaxPow_Chg_B7_31 : 32|16@1+ (1,-20000) [-20000|45535] "Kw"  PC
 SG_ M2P_PermitMaxPow_DisChg_B7_31 : 48|16@1+ (1,-20000) [-20000|45535] "Kw"  PC

BO_ 2335633041 M2P_SUMDATA47__01: 8 MBMU
 SG_ M2P_Power_B7_01 : 0|16@1+ (1,-20000) [-20000|45535] "Kw"  PC
 SG_ M2P_SysremEngy_Chg_B7_01 : 16|16@1+ (1,0) [0|65535] "Kwh"  PC
 SG_ M2P_SysremEngy_DisChg_B7_01 : 32|16@1+ (1,0) [0|65535] "Kwh"  PC
 SG_ M2P_SysMaxVolt_B7_01 : 48|16@1+ (1,0) [0|65535] "mv"  PC

BO_ 2335633042 M2P_SUMDATA47__02: 8 MBMU
 SG_ M2P_Power_B7_02 : 0|16@1+ (1,-20000) [-20000|45535] "Kw"  PC
 SG_ M2P_SysremEngy_Chg_B7_02 : 16|16@1+ (1,0) [0|65535] "Kwh"  PC
 SG_ M2P_SysremEngy_DisChg_B7_02 : 32|16@1+ (1,0) [0|65535] "Kwh"  PC
 SG_ M2P_SysMaxVolt_B7_02 : 48|16@1+ (1,0) [0|65535] "mv"  PC

BO_ 2335633043 M2P_SUMDATA47__03: 8 MBMU
 SG_ M2P_Power_B7_03 : 0|16@1+ (1,-20000) [-20000|45535] "Kw"  PC
 SG_ M2P_SysremEngy_Chg_B7_03 : 16|16@1+ (1,0) [0|65535] "Kwh"  PC
 SG_ M2P_SysremEngy_DisChg_B7_03 : 32|16@1+ (1,0) [0|65535] "Kwh"  PC
 SG_ M2P_SysMaxVolt_B7_03 : 48|16@1+ (1,0) [0|65535] "mv"  PC

BO_ 2335633044 M2P_SUMDATA47__04: 8 MBMU
 SG_ M2P_Power_B7_04 : 0|16@1+ (1,-20000) [-20000|45535] "Kw"  PC
 SG_ M2P_SysremEngy_Chg_B7_04 : 16|16@1+ (1,0) [0|65535] "Kwh"  PC
 SG_ M2P_SysremEngy_DisChg_B7_04 : 32|16@1+ (1,0) [0|65535] "Kwh"  PC
 SG_ M2P_SysMaxVolt_B7_04 : 48|16@1+ (1,0) [0|65535] "mv"  PC

BO_ 2335633045 M2P_SUMDATA47__05: 8 MBMU
 SG_ M2P_Power_B7_05 : 0|16@1+ (1,-20000) [-20000|45535] "Kw"  PC
 SG_ M2P_SysremEngy_Chg_B7_05 : 16|16@1+ (1,0) [0|65535] "Kwh"  PC
 SG_ M2P_SysremEngy_DisChg_B7_05 : 32|16@1+ (1,0) [0|65535] "Kwh"  PC
 SG_ M2P_SysMaxVolt_B7_05 : 48|16@1+ (1,0) [0|65535] "mv"  PC

BO_ 2335633046 M2P_SUMDATA47__06: 8 MBMU
 SG_ M2P_Power_B7_06 : 0|16@1+ (1,-20000) [-20000|45535] "Kw"  PC
 SG_ M2P_SysremEngy_Chg_B7_06 : 16|16@1+ (1,0) [0|65535] "Kwh"  PC
 SG_ M2P_SysremEngy_DisChg_B7_06 : 32|16@1+ (1,0) [0|65535] "Kwh"  PC
 SG_ M2P_SysMaxVolt_B7_06 : 48|16@1+ (1,0) [0|65535] "mv"  PC

BO_ 2335633047 M2P_SUMDATA47__07: 8 MBMU
 SG_ M2P_Power_B7_07 : 0|16@1+ (1,-20000) [-20000|45535] "Kw"  PC
 SG_ M2P_SysremEngy_Chg_B7_07 : 16|16@1+ (1,0) [0|65535] "Kwh"  PC
 SG_ M2P_SysremEngy_DisChg_B7_07 : 32|16@1+ (1,0) [0|65535] "Kwh"  PC
 SG_ M2P_SysMaxVolt_B7_07 : 48|16@1+ (1,0) [0|65535] "mv"  PC

BO_ 2335633048 M2P_SUMDATA47__08: 8 MBMU
 SG_ M2P_Power_B7_08 : 0|16@1+ (1,-20000) [-20000|45535] "Kw"  PC
 SG_ M2P_SysremEngy_Chg_B7_08 : 16|16@1+ (1,0) [0|65535] "Kwh"  PC
 SG_ M2P_SysremEngy_DisChg_B7_08 : 32|16@1+ (1,0) [0|65535] "Kwh"  PC
 SG_ M2P_SysMaxVolt_B7_08 : 48|16@1+ (1,0) [0|65535] "mv"  PC

BO_ 2335633049 M2P_SUMDATA47__09: 8 MBMU
 SG_ M2P_Power_B7_09 : 0|16@1+ (1,-20000) [-20000|45535] "Kw"  PC
 SG_ M2P_SysremEngy_Chg_B7_09 : 16|16@1+ (1,0) [0|65535] "Kwh"  PC
 SG_ M2P_SysremEngy_DisChg_B7_09 : 32|16@1+ (1,0) [0|65535] "Kwh"  PC
 SG_ M2P_SysMaxVolt_B7_09 : 48|16@1+ (1,0) [0|65535] "mv"  PC

BO_ 2335633050 M2P_SUMDATA47__10: 8 MBMU
 SG_ M2P_Power_B7_10 : 0|16@1+ (1,-20000) [-20000|45535] "Kw"  PC
 SG_ M2P_SysremEngy_Chg_B7_10 : 16|16@1+ (1,0) [0|65535] "Kwh"  PC
 SG_ M2P_SysremEngy_DisChg_B7_10 : 32|16@1+ (1,0) [0|65535] "Kwh"  PC
 SG_ M2P_SysMaxVolt_B7_10 : 48|16@1+ (1,0) [0|65535] "mv"  PC

BO_ 2335633051 M2P_SUMDATA47__11: 8 MBMU
 SG_ M2P_Power_B7_11 : 0|16@1+ (1,-20000) [-20000|45535] "Kw"  PC
 SG_ M2P_SysremEngy_Chg_B7_11 : 16|16@1+ (1,0) [0|65535] "Kwh"  PC
 SG_ M2P_SysremEngy_DisChg_B7_11 : 32|16@1+ (1,0) [0|65535] "Kwh"  PC
 SG_ M2P_SysMaxVolt_B7_11 : 48|16@1+ (1,0) [0|65535] "mv"  PC

BO_ 2335633052 M2P_SUMDATA47__12: 8 MBMU
 SG_ M2P_Power_B7_12 : 0|16@1+ (1,-20000) [-20000|45535] "Kw"  PC
 SG_ M2P_SysremEngy_Chg_B7_12 : 16|16@1+ (1,0) [0|65535] "Kwh"  PC
 SG_ M2P_SysremEngy_DisChg_B7_12 : 32|16@1+ (1,0) [0|65535] "Kwh"  PC
 SG_ M2P_SysMaxVolt_B7_12 : 48|16@1+ (1,0) [0|65535] "mv"  PC

BO_ 2335633053 M2P_SUMDATA47__13: 8 MBMU
 SG_ M2P_Power_B7_13 : 0|16@1+ (1,-20000) [-20000|45535] "Kw"  PC
 SG_ M2P_SysremEngy_Chg_B7_13 : 16|16@1+ (1,0) [0|65535] "Kwh"  PC
 SG_ M2P_SysremEngy_DisChg_B7_13 : 32|16@1+ (1,0) [0|65535] "Kwh"  PC
 SG_ M2P_SysMaxVolt_B7_13 : 48|16@1+ (1,0) [0|65535] "mv"  PC

BO_ 2335633054 M2P_SUMDATA47__14: 8 MBMU
 SG_ M2P_Power_B7_14 : 0|16@1+ (1,-20000) [-20000|45535] "Kw"  PC
 SG_ M2P_SysremEngy_Chg_B7_14 : 16|16@1+ (1,0) [0|65535] "Kwh"  PC
 SG_ M2P_SysremEngy_DisChg_B7_14 : 32|16@1+ (1,0) [0|65535] "Kwh"  PC
 SG_ M2P_SysMaxVolt_B7_14 : 48|16@1+ (1,0) [0|65535] "mv"  PC

BO_ 2335633055 M2P_SUMDATA47__15: 8 MBMU
 SG_ M2P_Power_B7_15 : 0|16@1+ (1,-20000) [-20000|45535] "Kw"  PC
 SG_ M2P_SysremEngy_Chg_B7_15 : 16|16@1+ (1,0) [0|65535] "Kwh"  PC
 SG_ M2P_SysremEngy_DisChg_B7_15 : 32|16@1+ (1,0) [0|65535] "Kwh"  PC
 SG_ M2P_SysMaxVolt_B7_15 : 48|16@1+ (1,0) [0|65535] "mv"  PC

BO_ 2335633056 M2P_SUMDATA47__16: 8 MBMU
 SG_ M2P_Power_B7_16 : 0|16@1+ (1,-20000) [-20000|45535] "Kw"  PC
 SG_ M2P_SysremEngy_Chg_B7_16 : 16|16@1+ (1,0) [0|65535] "Kwh"  PC
 SG_ M2P_SysremEngy_DisChg_B7_16 : 32|16@1+ (1,0) [0|65535] "Kwh"  PC
 SG_ M2P_SysMaxVolt_B7_16 : 48|16@1+ (1,0) [0|65535] "mv"  PC

BO_ 2335633057 M2P_SUMDATA47__17: 8 MBMU
 SG_ M2P_Power_B7_17 : 0|16@1+ (1,-20000) [-20000|45535] "Kw"  PC
 SG_ M2P_SysremEngy_Chg_B7_17 : 16|16@1+ (1,0) [0|65535] "Kwh"  PC
 SG_ M2P_SysremEngy_DisChg_B7_17 : 32|16@1+ (1,0) [0|65535] "Kwh"  PC
 SG_ M2P_SysMaxVolt_B7_17 : 48|16@1+ (1,0) [0|65535] "mv"  PC

BO_ 2335633058 M2P_SUMDATA47__18: 8 MBMU
 SG_ M2P_Power_B7_18 : 0|16@1+ (1,-20000) [-20000|45535] "Kw"  PC
 SG_ M2P_SysremEngy_Chg_B7_18 : 16|16@1+ (1,0) [0|65535] "Kwh"  PC
 SG_ M2P_SysremEngy_DisChg_B7_18 : 32|16@1+ (1,0) [0|65535] "Kwh"  PC
 SG_ M2P_SysMaxVolt_B7_18 : 48|16@1+ (1,0) [0|65535] "mv"  PC

BO_ 2335633059 M2P_SUMDATA47__19: 8 MBMU
 SG_ M2P_Power_B7_19 : 0|16@1+ (1,-20000) [-20000|45535] "Kw"  PC
 SG_ M2P_SysremEngy_Chg_B7_19 : 16|16@1+ (1,0) [0|65535] "Kwh"  PC
 SG_ M2P_SysremEngy_DisChg_B7_19 : 32|16@1+ (1,0) [0|65535] "Kwh"  PC
 SG_ M2P_SysMaxVolt_B7_19 : 48|16@1+ (1,0) [0|65535] "mv"  PC

BO_ 2335633060 M2P_SUMDATA47__20: 8 MBMU
 SG_ M2P_Power_B7_20 : 0|16@1+ (1,-20000) [-20000|45535] "Kw"  PC
 SG_ M2P_SysremEngy_Chg_B7_20 : 16|16@1+ (1,0) [0|65535] "Kwh"  PC
 SG_ M2P_SysremEngy_DisChg_B7_20 : 32|16@1+ (1,0) [0|65535] "Kwh"  PC
 SG_ M2P_SysMaxVolt_B7_20 : 48|16@1+ (1,0) [0|65535] "mv"  PC

BO_ 2335633061 M2P_SUMDATA47__21: 8 MBMU
 SG_ M2P_Power_B7_21 : 0|16@1+ (1,-20000) [-20000|45535] "Kw"  PC
 SG_ M2P_SysremEngy_Chg_B7_21 : 16|16@1+ (1,0) [0|65535] "Kwh"  PC
 SG_ M2P_SysremEngy_DisChg_B7_21 : 32|16@1+ (1,0) [0|65535] "Kwh"  PC
 SG_ M2P_SysMaxVolt_B7_21 : 48|16@1+ (1,0) [0|65535] "mv"  PC

BO_ 2335633062 M2P_SUMDATA47__22: 8 MBMU
 SG_ M2P_Power_B7_22 : 0|16@1+ (1,-20000) [-20000|45535] "Kw"  PC
 SG_ M2P_SysremEngy_Chg_B7_22 : 16|16@1+ (1,0) [0|65535] "Kwh"  PC
 SG_ M2P_SysremEngy_DisChg_B7_22 : 32|16@1+ (1,0) [0|65535] "Kwh"  PC
 SG_ M2P_SysMaxVolt_B7_22 : 48|16@1+ (1,0) [0|65535] "mv"  PC

BO_ 2335633063 M2P_SUMDATA47__23: 8 MBMU
 SG_ M2P_Power_B7_23 : 0|16@1+ (1,-20000) [-20000|45535] "Kw"  PC
 SG_ M2P_SysremEngy_Chg_B7_23 : 16|16@1+ (1,0) [0|65535] "Kwh"  PC
 SG_ M2P_SysremEngy_DisChg_B7_23 : 32|16@1+ (1,0) [0|65535] "Kwh"  PC
 SG_ M2P_SysMaxVolt_B7_23 : 48|16@1+ (1,0) [0|65535] "mv"  PC

BO_ 2335633064 M2P_SUMDATA47__24: 8 MBMU
 SG_ M2P_Power_B7_24 : 0|16@1+ (1,-20000) [-20000|45535] "Kw"  PC
 SG_ M2P_SysremEngy_Chg_B7_24 : 16|16@1+ (1,0) [0|65535] "Kwh"  PC
 SG_ M2P_SysremEngy_DisChg_B7_24 : 32|16@1+ (1,0) [0|65535] "Kwh"  PC
 SG_ M2P_SysMaxVolt_B7_24 : 48|16@1+ (1,0) [0|65535] "mv"  PC

BO_ 2335633065 M2P_SUMDATA47__25: 8 MBMU
 SG_ M2P_Power_B7_25 : 0|16@1+ (1,-20000) [-20000|45535] "Kw"  PC
 SG_ M2P_SysremEngy_Chg_B7_25 : 16|16@1+ (1,0) [0|65535] "Kwh"  PC
 SG_ M2P_SysremEngy_DisChg_B7_25 : 32|16@1+ (1,0) [0|65535] "Kwh"  PC
 SG_ M2P_SysMaxVolt_B7_25 : 48|16@1+ (1,0) [0|65535] "mv"  PC

BO_ 2335633066 M2P_SUMDATA47__26: 8 MBMU
 SG_ M2P_Power_B7_26 : 0|16@1+ (1,-20000) [-20000|45535] "Kw"  PC
 SG_ M2P_SysremEngy_Chg_B7_26 : 16|16@1+ (1,0) [0|65535] "Kwh"  PC
 SG_ M2P_SysremEngy_DisChg_B7_26 : 32|16@1+ (1,0) [0|65535] "Kwh"  PC
 SG_ M2P_SysMaxVolt_B7_26 : 48|16@1+ (1,0) [0|65535] "mv"  PC

BO_ 2335633067 M2P_SUMDATA47__27: 8 MBMU
 SG_ M2P_Power_B7_27 : 0|16@1+ (1,-20000) [-20000|45535] "Kw"  PC
 SG_ M2P_SysremEngy_Chg_B7_27 : 16|16@1+ (1,0) [0|65535] "Kwh"  PC
 SG_ M2P_SysremEngy_DisChg_B7_27 : 32|16@1+ (1,0) [0|65535] "Kwh"  PC
 SG_ M2P_SysMaxVolt_B7_27 : 48|16@1+ (1,0) [0|65535] "mv"  PC

BO_ 2335633068 M2P_SUMDATA47__28: 8 MBMU
 SG_ M2P_Power_B7_28 : 0|16@1+ (1,-20000) [-20000|45535] "Kw"  PC
 SG_ M2P_SysremEngy_Chg_B7_28 : 16|16@1+ (1,0) [0|65535] "Kwh"  PC
 SG_ M2P_SysremEngy_DisChg_B7_28 : 32|16@1+ (1,0) [0|65535] "Kwh"  PC
 SG_ M2P_SysMaxVolt_B7_28 : 48|16@1+ (1,0) [0|65535] "mv"  PC

BO_ 2335633069 M2P_SUMDATA47__29: 8 MBMU
 SG_ M2P_Power_B7_29 : 0|16@1+ (1,-20000) [-20000|45535] "Kw"  PC
 SG_ M2P_SysremEngy_Chg_B7_29 : 16|16@1+ (1,0) [0|65535] "Kwh"  PC
 SG_ M2P_SysremEngy_DisChg_B7_29 : 32|16@1+ (1,0) [0|65535] "Kwh"  PC
 SG_ M2P_SysMaxVolt_B7_29 : 48|16@1+ (1,0) [0|65535] "mv"  PC

BO_ 2335633070 M2P_SUMDATA47__30: 8 MBMU
 SG_ M2P_Power_B7_30 : 0|16@1+ (1,-20000) [-20000|45535] "Kw"  PC
 SG_ M2P_SysremEngy_Chg_B7_30 : 16|16@1+ (1,0) [0|65535] "Kwh"  PC
 SG_ M2P_SysremEngy_DisChg_B7_30 : 32|16@1+ (1,0) [0|65535] "Kwh"  PC
 SG_ M2P_SysMaxVolt_B7_30 : 48|16@1+ (1,0) [0|65535] "mv"  PC

BO_ 2335633071 M2P_SUMDATA47__31: 8 MBMU
 SG_ M2P_Power_B7_31 : 0|16@1+ (1,-20000) [-20000|45535] "Kw"  PC
 SG_ M2P_SysremEngy_Chg_B7_31 : 16|16@1+ (1,0) [0|65535] "Kwh"  PC
 SG_ M2P_SysremEngy_DisChg_B7_31 : 32|16@1+ (1,0) [0|65535] "Kwh"  PC
 SG_ M2P_SysMaxVolt_B7_31 : 48|16@1+ (1,0) [0|65535] "mv"  PC

BO_ 2335698577 M2P_SUMDATA48__01: 8 MBMU
 SG_ M2P_SysMinVolt_B7_01 : 0|16@1+ (1,0) [0|65535] "mv"  PC
 SG_ M2P_SysAvgVolt_B7_01 : 16|16@1+ (1,0) [0|65535] "mv"  PC
 SG_ M2P_BMS_Status_B7 : 32|3@1+ (1,0) [0|7] ""  PC
 SG_ M2P_SOC_B7 : 35|10@1+ (0.1,0) [0|102.3] "%"  PC
 SG_ M2P_SOH_B7 : 45|8@1+ (1,0) [0|255] "%"  PC
 SG_ Reserved_01 : 53|11@1+ (1,0) [0|2047] ""  PC

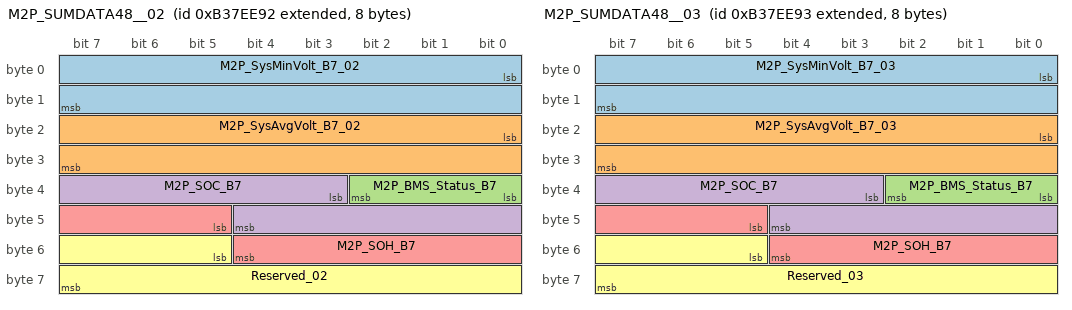
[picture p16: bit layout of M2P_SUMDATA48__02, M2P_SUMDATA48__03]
BO_ 2335698578 M2P_SUMDATA48__02: 8 MBMU
 SG_ M2P_SysMinVolt_B7_02 : 0|16@1+ (1,0) [0|65535] "mv"  PC
 SG_ M2P_SysAvgVolt_B7_02 : 16|16@1+ (1,0) [0|65535] "mv"  PC
 SG_ M2P_BMS_Status_B7 : 32|3@1+ (1,0) [0|7] ""  PC
 SG_ M2P_SOC_B7 : 35|10@1+ (0.1,0) [0|102.3] "%"  PC
 SG_ M2P_SOH_B7 : 45|8@1+ (1,0) [0|255] "%"  PC
 SG_ Reserved_02 : 53|11@1+ (1,0) [0|2047] ""  PC

BO_ 2335698579 M2P_SUMDATA48__03: 8 MBMU
 SG_ M2P_SysMinVolt_B7_03 : 0|16@1+ (1,0) [0|65535] "mv"  PC
 SG_ M2P_SysAvgVolt_B7_03 : 16|16@1+ (1,0) [0|65535] "mv"  PC
 SG_ M2P_BMS_Status_B7 : 32|3@1+ (1,0) [0|7] ""  PC
 SG_ M2P_SOC_B7 : 35|10@1+ (0.1,0) [0|102.3] "%"  PC
 SG_ M2P_SOH_B7 : 45|8@1+ (1,0) [0|255] "%"  PC
 SG_ Reserved_03 : 53|11@1+ (1,0) [0|2047] ""  PC

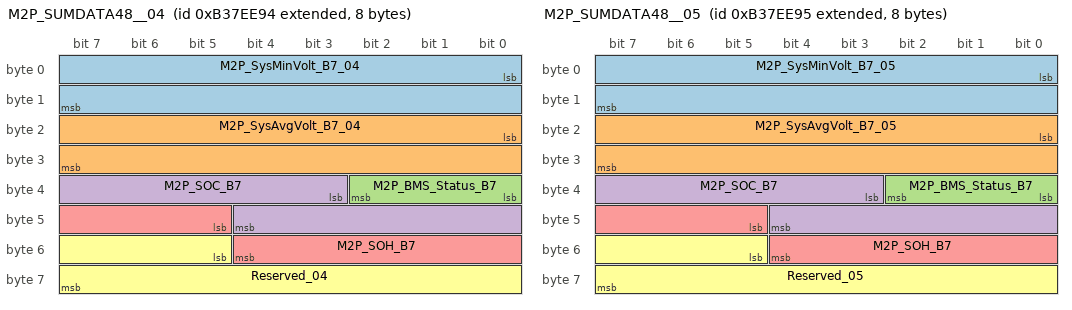
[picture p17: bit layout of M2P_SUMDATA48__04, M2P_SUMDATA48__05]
BO_ 2335698580 M2P_SUMDATA48__04: 8 MBMU
 SG_ M2P_SysMinVolt_B7_04 : 0|16@1+ (1,0) [0|65535] "mv"  PC
 SG_ M2P_SysAvgVolt_B7_04 : 16|16@1+ (1,0) [0|65535] "mv"  PC
 SG_ M2P_BMS_Status_B7 : 32|3@1+ (1,0) [0|7] ""  PC
 SG_ M2P_SOC_B7 : 35|10@1+ (0.1,0) [0|102.3] "%"  PC
 SG_ M2P_SOH_B7 : 45|8@1+ (1,0) [0|255] "%"  PC
 SG_ Reserved_04 : 53|11@1+ (1,0) [0|2047] ""  PC

BO_ 2335698581 M2P_SUMDATA48__05: 8 MBMU
 SG_ M2P_SysMinVolt_B7_05 : 0|16@1+ (1,0) [0|65535] "mv"  PC
 SG_ M2P_SysAvgVolt_B7_05 : 16|16@1+ (1,0) [0|65535] "mv"  PC
 SG_ M2P_BMS_Status_B7 : 32|3@1+ (1,0) [0|7] ""  PC
 SG_ M2P_SOC_B7 : 35|10@1+ (0.1,0) [0|102.3] "%"  PC
 SG_ M2P_SOH_B7 : 45|8@1+ (1,0) [0|255] "%"  PC
 SG_ Reserved_05 : 53|11@1+ (1,0) [0|2047] ""  PC

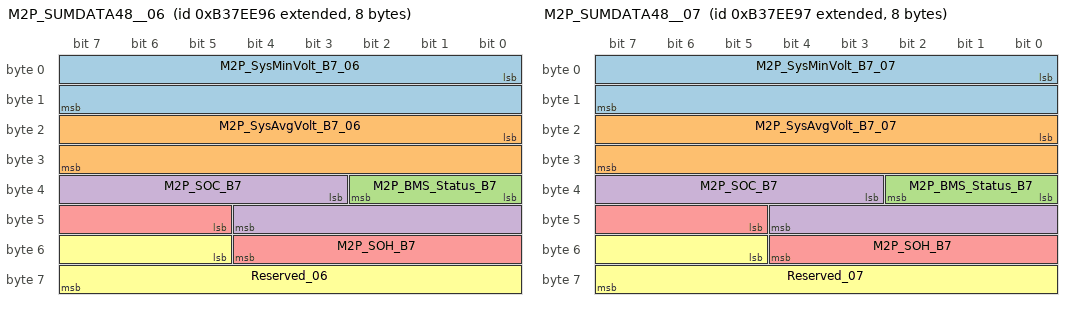
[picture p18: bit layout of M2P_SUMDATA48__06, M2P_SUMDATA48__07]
BO_ 2335698582 M2P_SUMDATA48__06: 8 MBMU
 SG_ M2P_SysMinVolt_B7_06 : 0|16@1+ (1,0) [0|65535] "mv"  PC
 SG_ M2P_SysAvgVolt_B7_06 : 16|16@1+ (1,0) [0|65535] "mv"  PC
 SG_ M2P_BMS_Status_B7 : 32|3@1+ (1,0) [0|7] ""  PC
 SG_ M2P_SOC_B7 : 35|10@1+ (0.1,0) [0|102.3] "%"  PC
 SG_ M2P_SOH_B7 : 45|8@1+ (1,0) [0|255] "%"  PC
 SG_ Reserved_06 : 53|11@1+ (1,0) [0|2047] ""  PC

BO_ 2335698583 M2P_SUMDATA48__07: 8 MBMU
 SG_ M2P_SysMinVolt_B7_07 : 0|16@1+ (1,0) [0|65535] "mv"  PC
 SG_ M2P_SysAvgVolt_B7_07 : 16|16@1+ (1,0) [0|65535] "mv"  PC
 SG_ M2P_BMS_Status_B7 : 32|3@1+ (1,0) [0|7] ""  PC
 SG_ M2P_SOC_B7 : 35|10@1+ (0.1,0) [0|102.3] "%"  PC
 SG_ M2P_SOH_B7 : 45|8@1+ (1,0) [0|255] "%"  PC
 SG_ Reserved_07 : 53|11@1+ (1,0) [0|2047] ""  PC

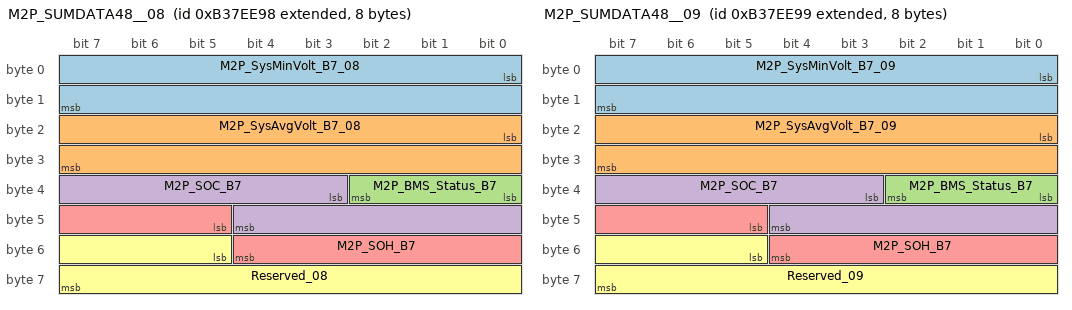
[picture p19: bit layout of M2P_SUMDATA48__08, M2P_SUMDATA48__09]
BO_ 2335698584 M2P_SUMDATA48__08: 8 MBMU
 SG_ M2P_SysMinVolt_B7_08 : 0|16@1+ (1,0) [0|65535] "mv"  PC
 SG_ M2P_SysAvgVolt_B7_08 : 16|16@1+ (1,0) [0|65535] "mv"  PC
 SG_ M2P_BMS_Status_B7 : 32|3@1+ (1,0) [0|7] ""  PC
 SG_ M2P_SOC_B7 : 35|10@1+ (0.1,0) [0|102.3] "%"  PC
 SG_ M2P_SOH_B7 : 45|8@1+ (1,0) [0|255] "%"  PC
 SG_ Reserved_08 : 53|11@1+ (1,0) [0|2047] ""  PC

BO_ 2335698585 M2P_SUMDATA48__09: 8 MBMU
 SG_ M2P_SysMinVolt_B7_09 : 0|16@1+ (1,0) [0|65535] "mv"  PC
 SG_ M2P_SysAvgVolt_B7_09 : 16|16@1+ (1,0) [0|65535] "mv"  PC
 SG_ M2P_BMS_Status_B7 : 32|3@1+ (1,0) [0|7] ""  PC
 SG_ M2P_SOC_B7 : 35|10@1+ (0.1,0) [0|102.3] "%"  PC
 SG_ M2P_SOH_B7 : 45|8@1+ (1,0) [0|255] "%"  PC
 SG_ Reserved_09 : 53|11@1+ (1,0) [0|2047] ""  PC

BO_ 2335698586 M2P_SUMDATA48__10: 8 MBMU
 SG_ M2P_SysMinVolt_B7_10 : 0|16@1+ (1,0) [0|65535] "mv"  PC
 SG_ M2P_SysAvgVolt_B7_10 : 16|16@1+ (1,0) [0|65535] "mv"  PC
 SG_ M2P_BMS_Status_B7 : 32|3@1+ (1,0) [0|7] ""  PC
 SG_ M2P_SOC_B7 : 35|10@1+ (0.1,0) [0|102.3] "%"  PC
 SG_ M2P_SOH_B7 : 45|8@1+ (1,0) [0|255] "%"  PC
 SG_ Reserved_10 : 53|11@1+ (1,0) [0|2047] ""  PC

BO_ 2335698587 M2P_SUMDATA48__11: 8 MBMU
 SG_ M2P_SysMinVolt_B7_11 : 0|16@1+ (1,0) [0|65535] "mv"  PC
 SG_ M2P_SysAvgVolt_B7_11 : 16|16@1+ (1,0) [0|65535] "mv"  PC
 SG_ M2P_BMS_Status_B7 : 32|3@1+ (1,0) [0|7] ""  PC
 SG_ M2P_SOC_B7 : 35|10@1+ (0.1,0) [0|102.3] "%"  PC
 SG_ M2P_SOH_B7 : 45|8@1+ (1,0) [0|255] "%"  PC
 SG_ Reserved_11 : 53|11@1+ (1,0) [0|2047] ""  PC

BO_ 2335698588 M2P_SUMDATA48__12: 8 MBMU
 SG_ M2P_SysMinVolt_B7_12 : 0|16@1+ (1,0) [0|65535] "mv"  PC
 SG_ M2P_SysAvgVolt_B7_12 : 16|16@1+ (1,0) [0|65535] "mv"  PC
 SG_ M2P_BMS_Status_B7 : 32|3@1+ (1,0) [0|7] ""  PC
 SG_ M2P_SOC_B7 : 35|10@1+ (0.1,0) [0|102.3] "%"  PC
 SG_ M2P_SOH_B7 : 45|8@1+ (1,0) [0|255] "%"  PC
 SG_ Reserved_12 : 53|11@1+ (1,0) [0|2047] ""  PC

BO_ 2335698589 M2P_SUMDATA48__13: 8 MBMU
 SG_ M2P_SysMinVolt_B7_13 : 0|16@1+ (1,0) [0|65535] "mv"  PC
 SG_ M2P_SysAvgVolt_B7_13 : 16|16@1+ (1,0) [0|65535] "mv"  PC
 SG_ M2P_BMS_Status_B7 : 32|3@1+ (1,0) [0|7] ""  PC
 SG_ M2P_SOC_B7 : 35|10@1+ (0.1,0) [0|102.3] "%"  PC
 SG_ M2P_SOH_B7 : 45|8@1+ (1,0) [0|255] "%"  PC
 SG_ Reserved_13 : 53|11@1+ (1,0) [0|2047] ""  PC

BO_ 2335698590 M2P_SUMDATA48__14: 8 MBMU
 SG_ M2P_SysMinVolt_B7_14 : 0|16@1+ (1,0) [0|65535] "mv"  PC
 SG_ M2P_SysAvgVolt_B7_14 : 16|16@1+ (1,0) [0|65535] "mv"  PC
 SG_ M2P_BMS_Status_B7 : 32|3@1+ (1,0) [0|7] ""  PC
 SG_ M2P_SOC_B7 : 35|10@1+ (0.1,0) [0|102.3] "%"  PC
 SG_ M2P_SOH_B7 : 45|8@1+ (1,0) [0|255] "%"  PC
 SG_ Reserved_14 : 53|11@1+ (1,0) [0|2047] ""  PC

BO_ 2335698591 M2P_SUMDATA48__15: 8 MBMU
 SG_ M2P_SysMinVolt_B7_15 : 0|16@1+ (1,0) [0|65535] "mv"  PC
 SG_ M2P_SysAvgVolt_B7_15 : 16|16@1+ (1,0) [0|65535] "mv"  PC
 SG_ M2P_BMS_Status_B7 : 32|3@1+ (1,0) [0|7] ""  PC
 SG_ M2P_SOC_B7 : 35|10@1+ (0.1,0) [0|102.3] "%"  PC
 SG_ M2P_SOH_B7 : 45|8@1+ (1,0) [0|255] "%"  PC
 SG_ Reserved_15 : 53|11@1+ (1,0) [0|2047] ""  PC

BO_ 2335698592 M2P_SUMDATA48__16: 8 MBMU
 SG_ M2P_SysMinVolt_B7_16 : 0|16@1+ (1,0) [0|65535] "mv"  PC
 SG_ M2P_SysAvgVolt_B7_16 : 16|16@1+ (1,0) [0|65535] "mv"  PC
 SG_ M2P_BMS_Status_B7 : 32|3@1+ (1,0) [0|7] ""  PC
 SG_ M2P_SOC_B7 : 35|10@1+ (0.1,0) [0|102.3] "%"  PC
 SG_ M2P_SOH_B7 : 45|8@1+ (1,0) [0|255] "%"  PC
 SG_ Reserved_16 : 53|11@1+ (1,0) [0|2047] ""  PC

BO_ 2335698593 M2P_SUMDATA48__17: 8 MBMU
 SG_ M2P_SysMinVolt_B7_17 : 0|16@1+ (1,0) [0|65535] "mv"  PC
 SG_ M2P_SysAvgVolt_B7_17 : 16|16@1+ (1,0) [0|65535] "mv"  PC
 SG_ M2P_BMS_Status_B7 : 32|3@1+ (1,0) [0|7] ""  PC
 SG_ M2P_SOC_B7 : 35|10@1+ (0.1,0) [0|102.3] "%"  PC
 SG_ M2P_SOH_B7 : 45|8@1+ (1,0) [0|255] "%"  PC
 SG_ Reserved_17 : 53|11@1+ (1,0) [0|2047] ""  PC

BO_ 2335698594 M2P_SUMDATA48__18: 8 MBMU
 SG_ M2P_SysMinVolt_B7_18 : 0|16@1+ (1,0) [0|65535] "mv"  PC
 SG_ M2P_SysAvgVolt_B7_18 : 16|16@1+ (1,0) [0|65535] "mv"  PC
 SG_ M2P_BMS_Status_B7 : 32|3@1+ (1,0) [0|7] ""  PC
 SG_ M2P_SOC_B7 : 35|10@1+ (0.1,0) [0|102.3] "%"  PC
 SG_ M2P_SOH_B7 : 45|8@1+ (1,0) [0|255] "%"  PC
 SG_ Reserved_18 : 53|11@1+ (1,0) [0|2047] ""  PC

BO_ 2335698595 M2P_SUMDATA48__19: 8 MBMU
 SG_ M2P_SysMinVolt_B7_19 : 0|16@1+ (1,0) [0|65535] "mv"  PC
 SG_ M2P_SysAvgVolt_B7_19 : 16|16@1+ (1,0) [0|65535] "mv"  PC
 SG_ M2P_BMS_Status_B7 : 32|3@1+ (1,0) [0|7] ""  PC
 SG_ M2P_SOC_B7 : 35|10@1+ (0.1,0) [0|102.3] "%"  PC
 SG_ M2P_SOH_B7 : 45|8@1+ (1,0) [0|255] "%"  PC
 SG_ Reserved_19 : 53|11@1+ (1,0) [0|2047] ""  PC

BO_ 2335698596 M2P_SUMDATA48__20: 8 MBMU
 SG_ M2P_SysMinVolt_B7_20 : 0|16@1+ (1,0) [0|65535] "mv"  PC
 SG_ M2P_SysAvgVolt_B7_20 : 16|16@1+ (1,0) [0|65535] "mv"  PC
 SG_ M2P_BMS_Status_B7 : 32|3@1+ (1,0) [0|7] ""  PC
 SG_ M2P_SOC_B7 : 35|10@1+ (0.1,0) [0|102.3] "%"  PC
 SG_ M2P_SOH_B7 : 45|8@1+ (1,0) [0|255] "%"  PC
 SG_ Reserved_20 : 53|11@1+ (1,0) [0|2047] ""  PC

BO_ 2335698597 M2P_SUMDATA48__21: 8 MBMU
 SG_ M2P_SysMinVolt_B7_21 : 0|16@1+ (1,0) [0|65535] "mv"  PC
 SG_ M2P_SysAvgVolt_B7_21 : 16|16@1+ (1,0) [0|65535] "mv"  PC
 SG_ M2P_BMS_Status_B7 : 32|3@1+ (1,0) [0|7] ""  PC
 SG_ M2P_SOC_B7 : 35|10@1+ (0.1,0) [0|102.3] "%"  PC
 SG_ M2P_SOH_B7 : 45|8@1+ (1,0) [0|255] "%"  PC
 SG_ Reserved_21 : 53|11@1+ (1,0) [0|2047] ""  PC

BO_ 2335698598 M2P_SUMDATA48__22: 8 MBMU
 SG_ M2P_SysMinVolt_B7_22 : 0|16@1+ (1,0) [0|65535] "mv"  PC
 SG_ M2P_SysAvgVolt_B7_22 : 16|16@1+ (1,0) [0|65535] "mv"  PC
 SG_ M2P_BMS_Status_B7 : 32|3@1+ (1,0) [0|7] ""  PC
 SG_ M2P_SOC_B7 : 35|10@1+ (0.1,0) [0|102.3] "%"  PC
 SG_ M2P_SOH_B7 : 45|8@1+ (1,0) [0|255] "%"  PC
 SG_ Reserved_22 : 53|11@1+ (1,0) [0|2047] ""  PC

BO_ 2335698599 M2P_SUMDATA48__23: 8 MBMU
 SG_ M2P_SysMinVolt_B7_23 : 0|16@1+ (1,0) [0|65535] "mv"  PC
 SG_ M2P_SysAvgVolt_B7_23 : 16|16@1+ (1,0) [0|65535] "mv"  PC
 SG_ M2P_BMS_Status_B7 : 32|3@1+ (1,0) [0|7] ""  PC
 SG_ M2P_SOC_B7 : 35|10@1+ (0.1,0) [0|102.3] "%"  PC
 SG_ M2P_SOH_B7 : 45|8@1+ (1,0) [0|255] "%"  PC
 SG_ Reserved_23 : 53|11@1+ (1,0) [0|2047] ""  PC

BO_ 2335698600 M2P_SUMDATA48__24: 8 MBMU
 SG_ M2P_SysMinVolt_B7_24 : 0|16@1+ (1,0) [0|65535] "mv"  PC
 SG_ M2P_SysAvgVolt_B7_24 : 16|16@1+ (1,0) [0|65535] "mv"  PC
 SG_ M2P_BMS_Status_B7 : 32|3@1+ (1,0) [0|7] ""  PC
 SG_ M2P_SOC_B7 : 35|10@1+ (0.1,0) [0|102.3] "%"  PC
 SG_ M2P_SOH_B7 : 45|8@1+ (1,0) [0|255] "%"  PC
 SG_ Reserved_24 : 53|11@1+ (1,0) [0|2047] ""  PC

BO_ 2335698601 M2P_SUMDATA48__25: 8 MBMU
 SG_ M2P_SysMinVolt_B7_25 : 0|16@1+ (1,0) [0|65535] "mv"  PC
 SG_ M2P_SysAvgVolt_B7_25 : 16|16@1+ (1,0) [0|65535] "mv"  PC
 SG_ M2P_BMS_Status_B7 : 32|3@1+ (1,0) [0|7] ""  PC
 SG_ M2P_SOC_B7 : 35|10@1+ (0.1,0) [0|102.3] "%"  PC
 SG_ M2P_SOH_B7 : 45|8@1+ (1,0) [0|255] "%"  PC
 SG_ Reserved_25 : 53|11@1+ (1,0) [0|2047] ""  PC

BO_ 2335698602 M2P_SUMDATA48__26: 8 MBMU
 SG_ M2P_SysMinVolt_B7_26 : 0|16@1+ (1,0) [0|65535] "mv"  PC
 SG_ M2P_SysAvgVolt_B7_26 : 16|16@1+ (1,0) [0|65535] "mv"  PC
 SG_ M2P_BMS_Status_B7 : 32|3@1+ (1,0) [0|7] ""  PC
 SG_ M2P_SOC_B7 : 35|10@1+ (0.1,0) [0|102.3] "%"  PC
 SG_ M2P_SOH_B7 : 45|8@1+ (1,0) [0|255] "%"  PC
 SG_ Reserved_26 : 53|11@1+ (1,0) [0|2047] ""  PC

BO_ 2335698603 M2P_SUMDATA48__27: 8 MBMU
 SG_ M2P_SysMinVolt_B7_27 : 0|16@1+ (1,0) [0|65535] "mv"  PC
 SG_ M2P_SysAvgVolt_B7_27 : 16|16@1+ (1,0) [0|65535] "mv"  PC
 SG_ M2P_BMS_Status_B7 : 32|3@1+ (1,0) [0|7] ""  PC
 SG_ M2P_SOC_B7 : 35|10@1+ (0.1,0) [0|102.3] "%"  PC
 SG_ M2P_SOH_B7 : 45|8@1+ (1,0) [0|255] "%"  PC
 SG_ Reserved_27 : 53|11@1+ (1,0) [0|2047] ""  PC

BO_ 2335698604 M2P_SUMDATA48__28: 8 MBMU
 SG_ M2P_SysMinVolt_B7_28 : 0|16@1+ (1,0) [0|65535] "mv"  PC
 SG_ M2P_SysAvgVolt_B7_28 : 16|16@1+ (1,0) [0|65535] "mv"  PC
 SG_ M2P_BMS_Status_B7 : 32|3@1+ (1,0) [0|7] ""  PC
 SG_ M2P_SOC_B7 : 35|10@1+ (0.1,0) [0|102.3] "%"  PC
 SG_ M2P_SOH_B7 : 45|8@1+ (1,0) [0|255] "%"  PC
 SG_ Reserved_28 : 53|11@1+ (1,0) [0|2047] ""  PC

BO_ 2335698605 M2P_SUMDATA48__29: 8 MBMU
 SG_ M2P_SysMinVolt_B7_29 : 0|16@1+ (1,0) [0|65535] "mv"  PC
 SG_ M2P_SysAvgVolt_B7_29 : 16|16@1+ (1,0) [0|65535] "mv"  PC
 SG_ M2P_BMS_Status_B7 : 32|3@1+ (1,0) [0|7] ""  PC
 SG_ M2P_SOC_B7 : 35|10@1+ (0.1,0) [0|102.3] "%"  PC
 SG_ M2P_SOH_B7 : 45|8@1+ (1,0) [0|255] "%"  PC
 SG_ Reserved_29 : 53|11@1+ (1,0) [0|2047] ""  PC

BO_ 2335698606 M2P_SUMDATA48__30: 8 MBMU
 SG_ M2P_SysMinVolt_B7_30 : 0|16@1+ (1,0) [0|65535] "mv"  PC
 SG_ M2P_SysAvgVolt_B7_30 : 16|16@1+ (1,0) [0|65535] "mv"  PC
 SG_ M2P_BMS_Status_B7 : 32|3@1+ (1,0) [0|7] ""  PC
 SG_ M2P_SOC_B7 : 35|10@1+ (0.1,0) [0|102.3] "%"  PC
 SG_ M2P_SOH_B7 : 45|8@1+ (1,0) [0|255] "%"  PC
 SG_ Reserved_30 : 53|11@1+ (1,0) [0|2047] ""  PC

BO_ 2335698607 M2P_SUMDATA48__31: 8 MBMU
 SG_ M2P_SysMinVolt_B7_31 : 0|16@1+ (1,0) [0|65535] "mv"  PC
 SG_ M2P_SysAvgVolt_B7_31 : 16|16@1+ (1,0) [0|65535] "mv"  PC
 SG_ M2P_BMS_Status_B7 : 32|3@1+ (1,0) [0|7] ""  PC
 SG_ M2P_SOC_B7 : 35|10@1+ (0.1,0) [0|102.3] "%"  PC
 SG_ M2P_SOH_B7 : 45|8@1+ (1,0) [0|255] "%"  PC
 SG_ Reserved_31 : 53|11@1+ (1,0) [0|2047] ""  PC

BO_ 2335764113 M2P_SUMDATA49__01: 8 MBMU
 SG_ M2P_SOE_Charge_B7 : 0|10@1+ (0.1,0) [0|102.3] "%"  PC
 SG_ M2P_SOE_Discharge_B7 : 10|10@1+ (0.1,0) [0|102.3] "%"  PC
 SG_ Reserved_01 : 20|44@1+ (1,0) [0|17592186044415] ""  PC

BO_ 2335764114 M2P_SUMDATA49__02: 8 MBMU
 SG_ M2P_SOE_Charge_B7 : 0|10@1+ (0.1,0) [0|102.3] "%"  PC
 SG_ M2P_SOE_Discharge_B7 : 10|10@1+ (0.1,0) [0|102.3] "%"  PC
 SG_ Reserved_02 : 20|44@1+ (1,0) [0|17592186044415] ""  PC

BO_ 2335764115 M2P_SUMDATA49__03: 8 MBMU
 SG_ M2P_SOE_Charge_B7 : 0|10@1+ (0.1,0) [0|102.3] "%"  PC
 SG_ M2P_SOE_Discharge_B7 : 10|10@1+ (0.1,0) [0|102.3] "%"  PC
 SG_ Reserved_03 : 20|44@1+ (1,0) [0|17592186044415] ""  PC

BO_ 2335764116 M2P_SUMDATA49__04: 8 MBMU
 SG_ M2P_SOE_Charge_B7 : 0|10@1+ (0.1,0) [0|102.3] "%"  PC
 SG_ M2P_SOE_Discharge_B7 : 10|10@1+ (0.1,0) [0|102.3] "%"  PC
 SG_ Reserved_04 : 20|44@1+ (1,0) [0|17592186044415] ""  PC

BO_ 2335764117 M2P_SUMDATA49__05: 8 MBMU
 SG_ M2P_SOE_Charge_B7 : 0|10@1+ (0.1,0) [0|102.3] "%"  PC
 SG_ M2P_SOE_Discharge_B7 : 10|10@1+ (0.1,0) [0|102.3] "%"  PC
 SG_ Reserved_05 : 20|44@1+ (1,0) [0|17592186044415] ""  PC

BO_ 2335764118 M2P_SUMDATA49__06: 8 MBMU
 SG_ M2P_SOE_Charge_B7 : 0|10@1+ (0.1,0) [0|102.3] "%"  PC
 SG_ M2P_SOE_Discharge_B7 : 10|10@1+ (0.1,0) [0|102.3] "%"  PC
 SG_ Reserved_06 : 20|44@1+ (1,0) [0|17592186044415] ""  PC

BO_ 2335764119 M2P_SUMDATA49__07: 8 MBMU
 SG_ M2P_SOE_Charge_B7 : 0|10@1+ (0.1,0) [0|102.3] "%"  PC
 SG_ M2P_SOE_Discharge_B7 : 10|10@1+ (0.1,0) [0|102.3] "%"  PC
 SG_ Reserved_07 : 20|44@1+ (1,0) [0|17592186044415] ""  PC

BO_ 2335764120 M2P_SUMDATA49__08: 8 MBMU
 SG_ M2P_SOE_Charge_B7 : 0|10@1+ (0.1,0) [0|102.3] "%"  PC
 SG_ M2P_SOE_Discharge_B7 : 10|10@1+ (0.1,0) [0|102.3] "%"  PC
 SG_ Reserved_08 : 20|44@1+ (1,0) [0|17592186044415] ""  PC

BO_ 2335764121 M2P_SUMDATA49__09: 8 MBMU
 SG_ M2P_SOE_Charge_B7 : 0|10@1+ (0.1,0) [0|102.3] "%"  PC
 SG_ M2P_SOE_Discharge_B7 : 10|10@1+ (0.1,0) [0|102.3] "%"  PC
 SG_ Reserved_09 : 20|44@1+ (1,0) [0|17592186044415] ""  PC

BO_ 2335764122 M2P_SUMDATA49__10: 8 MBMU
 SG_ M2P_SOE_Charge_B7 : 0|10@1+ (0.1,0) [0|102.3] "%"  PC
 SG_ M2P_SOE_Discharge_B7 : 10|10@1+ (0.1,0) [0|102.3] "%"  PC
 SG_ Reserved_10 : 20|44@1+ (1,0) [0|17592186044415] ""  PC

BO_ 2335764123 M2P_SUMDATA49__11: 8 MBMU
 SG_ M2P_SOE_Charge_B7 : 0|10@1+ (0.1,0) [0|102.3] "%"  PC
 SG_ M2P_SOE_Discharge_B7 : 10|10@1+ (0.1,0) [0|102.3] "%"  PC
 SG_ Reserved_11 : 20|44@1+ (1,0) [0|17592186044415] ""  PC

BO_ 2335764124 M2P_SUMDATA49__12: 8 MBMU
 SG_ M2P_SOE_Charge_B7 : 0|10@1+ (0.1,0) [0|102.3] "%"  PC
 SG_ M2P_SOE_Discharge_B7 : 10|10@1+ (0.1,0) [0|102.3] "%"  PC
 SG_ Reserved_12 : 20|44@1+ (1,0) [0|17592186044415] ""  PC

BO_ 2335764125 M2P_SUMDATA49__13: 8 MBMU
 SG_ M2P_SOE_Charge_B7 : 0|10@1+ (0.1,0) [0|102.3] "%"  PC
 SG_ M2P_SOE_Discharge_B7 : 10|10@1+ (0.1,0) [0|102.3] "%"  PC
 SG_ Reserved_13 : 20|44@1+ (1,0) [0|17592186044415] ""  PC

BO_ 2335764126 M2P_SUMDATA49__14: 8 MBMU
 SG_ M2P_SOE_Charge_B7 : 0|10@1+ (0.1,0) [0|102.3] "%"  PC
 SG_ M2P_SOE_Discharge_B7 : 10|10@1+ (0.1,0) [0|102.3] "%"  PC
 SG_ Reserved_14 : 20|44@1+ (1,0) [0|17592186044415] ""  PC

BO_ 2335764127 M2P_SUMDATA49__15: 8 MBMU
 SG_ M2P_SOE_Charge_B7 : 0|10@1+ (0.1,0) [0|102.3] "%"  PC
 SG_ M2P_SOE_Discharge_B7 : 10|10@1+ (0.1,0) [0|102.3] "%"  PC
 SG_ Reserved_15 : 20|44@1+ (1,0) [0|17592186044415] ""  PC

BO_ 2335764128 M2P_SUMDATA49__16: 8 MBMU
 SG_ M2P_SOE_Charge_B7 : 0|10@1+ (0.1,0) [0|102.3] "%"  PC
 SG_ M2P_SOE_Discharge_B7 : 10|10@1+ (0.1,0) [0|102.3] "%"  PC
 SG_ Reserved_16 : 20|44@1+ (1,0) [0|17592186044415] ""  PC

BO_ 2335764129 M2P_SUMDATA49__17: 8 MBMU
 SG_ M2P_SOE_Charge_B7 : 0|10@1+ (0.1,0) [0|102.3] "%"  PC
 SG_ M2P_SOE_Discharge_B7 : 10|10@1+ (0.1,0) [0|102.3] "%"  PC
 SG_ Reserved_17 : 20|44@1+ (1,0) [0|17592186044415] ""  PC

BO_ 2335764130 M2P_SUMDATA49__18: 8 MBMU
 SG_ M2P_SOE_Charge_B7 : 0|10@1+ (0.1,0) [0|102.3] "%"  PC
 SG_ M2P_SOE_Discharge_B7 : 10|10@1+ (0.1,0) [0|102.3] "%"  PC
 SG_ Reserved_18 : 20|44@1+ (1,0) [0|17592186044415] ""  PC

BO_ 2335764131 M2P_SUMDATA49__19: 8 MBMU
 SG_ M2P_SOE_Charge_B7 : 0|10@1+ (0.1,0) [0|102.3] "%"  PC
 SG_ M2P_SOE_Discharge_B7 : 10|10@1+ (0.1,0) [0|102.3] "%"  PC
 SG_ Reserved_19 : 20|44@1+ (1,0) [0|17592186044415] ""  PC

BO_ 2335764132 M2P_SUMDATA49__20: 8 MBMU
 SG_ M2P_SOE_Charge_B7 : 0|10@1+ (0.1,0) [0|102.3] "%"  PC
 SG_ M2P_SOE_Discharge_B7 : 10|10@1+ (0.1,0) [0|102.3] "%"  PC
 SG_ Reserved_20 : 20|44@1+ (1,0) [0|17592186044415] ""  PC

BO_ 2335764133 M2P_SUMDATA49__21: 8 MBMU
 SG_ M2P_SOE_Charge_B7 : 0|10@1+ (0.1,0) [0|102.3] "%"  PC
 SG_ M2P_SOE_Discharge_B7 : 10|10@1+ (0.1,0) [0|102.3] "%"  PC
 SG_ Reserved_21 : 20|44@1+ (1,0) [0|17592186044415] ""  PC

BO_ 2335764134 M2P_SUMDATA49__22: 8 MBMU
 SG_ M2P_SOE_Charge_B7 : 0|10@1+ (0.1,0) [0|102.3] "%"  PC
 SG_ M2P_SOE_Discharge_B7 : 10|10@1+ (0.1,0) [0|102.3] "%"  PC
 SG_ Reserved_22 : 20|44@1+ (1,0) [0|17592186044415] ""  PC

BO_ 2335764135 M2P_SUMDATA49__23: 8 MBMU
 SG_ M2P_SOE_Charge_B7 : 0|10@1+ (0.1,0) [0|102.3] "%"  PC
 SG_ M2P_SOE_Discharge_B7 : 10|10@1+ (0.1,0) [0|102.3] "%"  PC
 SG_ Reserved_23 : 20|44@1+ (1,0) [0|17592186044415] ""  PC

BO_ 2335764136 M2P_SUMDATA49__24: 8 MBMU
 SG_ M2P_SOE_Charge_B7 : 0|10@1+ (0.1,0) [0|102.3] "%"  PC
 SG_ M2P_SOE_Discharge_B7 : 10|10@1+ (0.1,0) [0|102.3] "%"  PC
 SG_ Reserved_24 : 20|44@1+ (1,0) [0|17592186044415] ""  PC

BO_ 2335764137 M2P_SUMDATA49__25: 8 MBMU
 SG_ M2P_SOE_Charge_B7 : 0|10@1+ (0.1,0) [0|102.3] "%"  PC
 SG_ M2P_SOE_Discharge_B7 : 10|10@1+ (0.1,0) [0|102.3] "%"  PC
 SG_ Reserved_25 : 20|44@1+ (1,0) [0|17592186044415] ""  PC

BO_ 2335764138 M2P_SUMDATA49__26: 8 MBMU
 SG_ M2P_SOE_Charge_B7 : 0|10@1+ (0.1,0) [0|102.3] "%"  PC
 SG_ M2P_SOE_Discharge_B7 : 10|10@1+ (0.1,0) [0|102.3] "%"  PC
 SG_ Reserved_26 : 20|44@1+ (1,0) [0|17592186044415] ""  PC

BO_ 2335764139 M2P_SUMDATA49__27: 8 MBMU
 SG_ M2P_SOE_Charge_B7 : 0|10@1+ (0.1,0) [0|102.3] "%"  PC
 SG_ M2P_SOE_Discharge_B7 : 10|10@1+ (0.1,0) [0|102.3] "%"  PC
 SG_ Reserved_27 : 20|44@1+ (1,0) [0|17592186044415] ""  PC

BO_ 2335764140 M2P_SUMDATA49__28: 8 MBMU
 SG_ M2P_SOE_Charge_B7 : 0|10@1+ (0.1,0) [0|102.3] "%"  PC
 SG_ M2P_SOE_Discharge_B7 : 10|10@1+ (0.1,0) [0|102.3] "%"  PC
 SG_ Reserved_28 : 20|44@1+ (1,0) [0|17592186044415] ""  PC

BO_ 2335764141 M2P_SUMDATA49__29: 8 MBMU
 SG_ M2P_SOE_Charge_B7 : 0|10@1+ (0.1,0) [0|102.3] "%"  PC
 SG_ M2P_SOE_Discharge_B7 : 10|10@1+ (0.1,0) [0|102.3] "%"  PC
 SG_ Reserved_29 : 20|44@1+ (1,0) [0|17592186044415] ""  PC

BO_ 2335764142 M2P_SUMDATA49__30: 8 MBMU
 SG_ M2P_SOE_Charge_B7 : 0|10@1+ (0.1,0) [0|102.3] "%"  PC
 SG_ M2P_SOE_Discharge_B7 : 10|10@1+ (0.1,0) [0|102.3] "%"  PC
 SG_ Reserved_30 : 20|44@1+ (1,0) [0|17592186044415] ""  PC

BO_ 2335764143 M2P_SUMDATA49__31: 8 MBMU
 SG_ M2P_SOE_Charge_B7 : 0|10@1+ (0.1,0) [0|102.3] "%"  PC
 SG_ M2P_SOE_Discharge_B7 : 10|10@1+ (0.1,0) [0|102.3] "%"  PC
 SG_ Reserved_31 : 20|44@1+ (1,0) [0|17592186044415] ""  PC

BO_ 2335829649 M2P_SUMDATA50__01: 8 MBMU
 SG_ M2P_Measure_Vol_B8_01 : 0|16@1+ (0.1,0) [0|6553.5] "V"  PC,SBMU
 SG_ M2P_Current_B8_01 : 16|16@1+ (1,-20000) [-20000|45535] "A"  PC,SBMU
 SG_ M2P_PermitMaxCharge_I_B8_01 : 32|16@1+ (1,-20000) [-20000|45535] "A"  PC
 SG_ M2P_PermitMaxDisCharge_I_B8_01 : 48|16@1+ (1,-20000) [-20000|45535] "A"  PC

BO_ 2335829650 M2P_SUMDATA50__02: 8 MBMU
 SG_ M2P_Measure_Vol_B8_02 : 0|16@1+ (0.1,0) [0|6553.5] "V"  PC,SBMU
 SG_ M2P_Current_B8_02 : 16|16@1+ (1,-20000) [-20000|45535] "A"  PC,SBMU
 SG_ M2P_PermitMaxCharge_I_B8_02 : 32|16@1+ (1,-20000) [-20000|45535] "A"  PC
 SG_ M2P_PermitMaxDisCharge_I_B8_02 : 48|16@1+ (1,-20000) [-20000|45535] "A"  PC

BO_ 2335829651 M2P_SUMDATA50__03: 8 MBMU
 SG_ M2P_Measure_Vol_B8_03 : 0|16@1+ (0.1,0) [0|6553.5] "V"  PC,SBMU
 SG_ M2P_Current_B8_03 : 16|16@1+ (1,-20000) [-20000|45535] "A"  PC,SBMU
 SG_ M2P_PermitMaxCharge_I_B8_03 : 32|16@1+ (1,-20000) [-20000|45535] "A"  PC
 SG_ M2P_PermitMaxDisCharge_I_B8_03 : 48|16@1+ (1,-20000) [-20000|45535] "A"  PC

BO_ 2335829652 M2P_SUMDATA50__04: 8 MBMU
 SG_ M2P_Measure_Vol_B8_04 : 0|16@1+ (0.1,0) [0|6553.5] "V"  PC,SBMU
 SG_ M2P_Current_B8_04 : 16|16@1+ (1,-20000) [-20000|45535] "A"  PC,SBMU
 SG_ M2P_PermitMaxCharge_I_B8_04 : 32|16@1+ (1,-20000) [-20000|45535] "A"  PC
 SG_ M2P_PermitMaxDisCharge_I_B8_04 : 48|16@1+ (1,-20000) [-20000|45535] "A"  PC

BO_ 2335829653 M2P_SUMDATA50__05: 8 MBMU
 SG_ M2P_Measure_Vol_B8_05 : 0|16@1+ (0.1,0) [0|6553.5] "V"  PC,SBMU
 SG_ M2P_Current_B8_05 : 16|16@1+ (1,-20000) [-20000|45535] "A"  PC,SBMU
 SG_ M2P_PermitMaxCharge_I_B8_05 : 32|16@1+ (1,-20000) [-20000|45535] "A"  PC
 SG_ M2P_PermitMaxDisCharge_I_B8_05 : 48|16@1+ (1,-20000) [-20000|45535] "A"  PC

BO_ 2335829654 M2P_SUMDATA50__06: 8 MBMU
 SG_ M2P_Measure_Vol_B8_06 : 0|16@1+ (0.1,0) [0|6553.5] "V"  PC,SBMU
 SG_ M2P_Current_B8_06 : 16|16@1+ (1,-20000) [-20000|45535] "A"  PC,SBMU
 SG_ M2P_PermitMaxCharge_I_B8_06 : 32|16@1+ (1,-20000) [-20000|45535] "A"  PC
 SG_ M2P_PermitMaxDisCharge_I_B8_06 : 48|16@1+ (1,-20000) [-20000|45535] "A"  PC

BO_ 2335829655 M2P_SUMDATA50__07: 8 MBMU
 SG_ M2P_Measure_Vol_B8_07 : 0|16@1+ (0.1,0) [0|6553.5] "V"  PC,SBMU
 SG_ M2P_Current_B8_07 : 16|16@1+ (1,-20000) [-20000|45535] "A"  PC,SBMU
 SG_ M2P_PermitMaxCharge_I_B8_07 : 32|16@1+ (1,-20000) [-20000|45535] "A"  PC
 SG_ M2P_PermitMaxDisCharge_I_B8_07 : 48|16@1+ (1,-20000) [-20000|45535] "A"  PC

BO_ 2335829656 M2P_SUMDATA50__08: 8 MBMU
 SG_ M2P_Measure_Vol_B8_08 : 0|16@1+ (0.1,0) [0|6553.5] "V"  PC,SBMU
 SG_ M2P_Current_B8_08 : 16|16@1+ (1,-20000) [-20000|45535] "A"  PC,SBMU
 SG_ M2P_PermitMaxCharge_I_B8_08 : 32|16@1+ (1,-20000) [-20000|45535] "A"  PC
 SG_ M2P_PermitMaxDisCharge_I_B8_08 : 48|16@1+ (1,-20000) [-20000|45535] "A"  PC

BO_ 2335829657 M2P_SUMDATA50__09: 8 MBMU
 SG_ M2P_Measure_Vol_B8_09 : 0|16@1+ (0.1,0) [0|6553.5] "V"  PC,SBMU
 SG_ M2P_Current_B8_09 : 16|16@1+ (1,-20000) [-20000|45535] "A"  PC,SBMU
 SG_ M2P_PermitMaxCharge_I_B8_09 : 32|16@1+ (1,-20000) [-20000|45535] "A"  PC
 SG_ M2P_PermitMaxDisCharge_I_B8_09 : 48|16@1+ (1,-20000) [-20000|45535] "A"  PC

BO_ 2335829658 M2P_SUMDATA50__10: 8 MBMU
 SG_ M2P_Measure_Vol_B8_10 : 0|16@1+ (0.1,0) [0|6553.5] "V"  PC,SBMU
 SG_ M2P_Current_B8_10 : 16|16@1+ (1,-20000) [-20000|45535] "A"  PC,SBMU
 SG_ M2P_PermitMaxCharge_I_B8_10 : 32|16@1+ (1,-20000) [-20000|45535] "A"  PC
 SG_ M2P_PermitMaxDisCharge_I_B8_10 : 48|16@1+ (1,-20000) [-20000|45535] "A"  PC

BO_ 2335829659 M2P_SUMDATA50__11: 8 MBMU
 SG_ M2P_Measure_Vol_B8_11 : 0|16@1+ (0.1,0) [0|6553.5] "V"  PC,SBMU
 SG_ M2P_Current_B8_11 : 16|16@1+ (1,-20000) [-20000|45535] "A"  PC,SBMU
 SG_ M2P_PermitMaxCharge_I_B8_11 : 32|16@1+ (1,-20000) [-20000|45535] "A"  PC
 SG_ M2P_PermitMaxDisCharge_I_B8_11 : 48|16@1+ (1,-20000) [-20000|45535] "A"  PC

BO_ 2335829660 M2P_SUMDATA50__12: 8 MBMU
 SG_ M2P_Measure_Vol_B8_12 : 0|16@1+ (0.1,0) [0|6553.5] "V"  PC,SBMU
 SG_ M2P_Current_B8_12 : 16|16@1+ (1,-20000) [-20000|45535] "A"  PC,SBMU
 SG_ M2P_PermitMaxCharge_I_B8_12 : 32|16@1+ (1,-20000) [-20000|45535] "A"  PC
 SG_ M2P_PermitMaxDisCharge_I_B8_12 : 48|16@1+ (1,-20000) [-20000|45535] "A"  PC

BO_ 2335829661 M2P_SUMDATA50__13: 8 MBMU
 SG_ M2P_Measure_Vol_B8_13 : 0|16@1+ (0.1,0) [0|6553.5] "V"  PC,SBMU
 SG_ M2P_Current_B8_13 : 16|16@1+ (1,-20000) [-20000|45535] "A"  PC,SBMU
 SG_ M2P_PermitMaxCharge_I_B8_13 : 32|16@1+ (1,-20000) [-20000|45535] "A"  PC
 SG_ M2P_PermitMaxDisCharge_I_B8_13 : 48|16@1+ (1,-20000) [-20000|45535] "A"  PC

BO_ 2335829662 M2P_SUMDATA50__14: 8 MBMU
 SG_ M2P_Measure_Vol_B8_14 : 0|16@1+ (0.1,0) [0|6553.5] "V"  PC,SBMU
 SG_ M2P_Current_B8_14 : 16|16@1+ (1,-20000) [-20000|45535] "A"  PC,SBMU
 SG_ M2P_PermitMaxCharge_I_B8_14 : 32|16@1+ (1,-20000) [-20000|45535] "A"  PC
 SG_ M2P_PermitMaxDisCharge_I_B8_14 : 48|16@1+ (1,-20000) [-20000|45535] "A"  PC

BO_ 2335829663 M2P_SUMDATA50__15: 8 MBMU
 SG_ M2P_Measure_Vol_B8_15 : 0|16@1+ (0.1,0) [0|6553.5] "V"  PC,SBMU
 SG_ M2P_Current_B8_15 : 16|16@1+ (1,-20000) [-20000|45535] "A"  PC,SBMU
 SG_ M2P_PermitMaxCharge_I_B8_15 : 32|16@1+ (1,-20000) [-20000|45535] "A"  PC
 SG_ M2P_PermitMaxDisCharge_I_B8_15 : 48|16@1+ (1,-20000) [-20000|45535] "A"  PC

BO_ 2335829664 M2P_SUMDATA50__16: 8 MBMU
 SG_ M2P_Measure_Vol_B8_16 : 0|16@1+ (0.1,0) [0|6553.5] "V"  PC,SBMU
 SG_ M2P_Current_B8_16 : 16|16@1+ (1,-20000) [-20000|45535] "A"  PC,SBMU
 SG_ M2P_PermitMaxCharge_I_B8_16 : 32|16@1+ (1,-20000) [-20000|45535] "A"  PC
 SG_ M2P_PermitMaxDisCharge_I_B8_16 : 48|16@1+ (1,-20000) [-20000|45535] "A"  PC

BO_ 2335829665 M2P_SUMDATA50__17: 8 MBMU
 SG_ M2P_Measure_Vol_B8_17 : 0|16@1+ (0.1,0) [0|6553.5] "V"  PC,SBMU
 SG_ M2P_Current_B8_17 : 16|16@1+ (1,-20000) [-20000|45535] "A"  PC,SBMU
 SG_ M2P_PermitMaxCharge_I_B8_17 : 32|16@1+ (1,-20000) [-20000|45535] "A"  PC
 SG_ M2P_PermitMaxDisCharge_I_B8_17 : 48|16@1+ (1,-20000) [-20000|45535] "A"  PC

BO_ 2335829666 M2P_SUMDATA50__18: 8 MBMU
 SG_ M2P_Measure_Vol_B8_18 : 0|16@1+ (0.1,0) [0|6553.5] "V"  PC,SBMU
 SG_ M2P_Current_B8_18 : 16|16@1+ (1,-20000) [-20000|45535] "A"  PC,SBMU
 SG_ M2P_PermitMaxCharge_I_B8_18 : 32|16@1+ (1,-20000) [-20000|45535] "A"  PC
 SG_ M2P_PermitMaxDisCharge_I_B8_18 : 48|16@1+ (1,-20000) [-20000|45535] "A"  PC

BO_ 2335829667 M2P_SUMDATA50__19: 8 MBMU
 SG_ M2P_Measure_Vol_B8_19 : 0|16@1+ (0.1,0) [0|6553.5] "V"  PC,SBMU
 SG_ M2P_Current_B8_19 : 16|16@1+ (1,-20000) [-20000|45535] "A"  PC,SBMU
 SG_ M2P_PermitMaxCharge_I_B8_19 : 32|16@1+ (1,-20000) [-20000|45535] "A"  PC
 SG_ M2P_PermitMaxDisCharge_I_B8_19 : 48|16@1+ (1,-20000) [-20000|45535] "A"  PC

BO_ 2335829668 M2P_SUMDATA50__20: 8 MBMU
 SG_ M2P_Measure_Vol_B8_20 : 0|16@1+ (0.1,0) [0|6553.5] "V"  PC,SBMU
 SG_ M2P_Current_B8_20 : 16|16@1+ (1,-20000) [-20000|45535] "A"  PC,SBMU
 SG_ M2P_PermitMaxCharge_I_B8_20 : 32|16@1+ (1,-20000) [-20000|45535] "A"  PC
 SG_ M2P_PermitMaxDisCharge_I_B8_20 : 48|16@1+ (1,-20000) [-20000|45535] "A"  PC

BO_ 2335829669 M2P_SUMDATA50__21: 8 MBMU
 SG_ M2P_Measure_Vol_B8_21 : 0|16@1+ (0.1,0) [0|6553.5] "V"  PC,SBMU
 SG_ M2P_Current_B8_21 : 16|16@1+ (1,-20000) [-20000|45535] "A"  PC,SBMU
 SG_ M2P_PermitMaxCharge_I_B8_21 : 32|16@1+ (1,-20000) [-20000|45535] "A"  PC
 SG_ M2P_PermitMaxDisCharge_I_B8_21 : 48|16@1+ (1,-20000) [-20000|45535] "A"  PC

BO_ 2335829670 M2P_SUMDATA50__22: 8 MBMU
 SG_ M2P_Measure_Vol_B8_22 : 0|16@1+ (0.1,0) [0|6553.5] "V"  PC,SBMU
 SG_ M2P_Current_B8_22 : 16|16@1+ (1,-20000) [-20000|45535] "A"  PC,SBMU
 SG_ M2P_PermitMaxCharge_I_B8_22 : 32|16@1+ (1,-20000) [-20000|45535] "A"  PC
 SG_ M2P_PermitMaxDisCharge_I_B8_22 : 48|16@1+ (1,-20000) [-20000|45535] "A"  PC

BO_ 2335829671 M2P_SUMDATA50__23: 8 MBMU
 SG_ M2P_Measure_Vol_B8_23 : 0|16@1+ (0.1,0) [0|6553.5] "V"  PC,SBMU
 SG_ M2P_Current_B8_23 : 16|16@1+ (1,-20000) [-20000|45535] "A"  PC,SBMU
 SG_ M2P_PermitMaxCharge_I_B8_23 : 32|16@1+ (1,-20000) [-20000|45535] "A"  PC
 SG_ M2P_PermitMaxDisCharge_I_B8_23 : 48|16@1+ (1,-20000) [-20000|45535] "A"  PC

BO_ 2335829672 M2P_SUMDATA50__24: 8 MBMU
 SG_ M2P_Measure_Vol_B8_24 : 0|16@1+ (0.1,0) [0|6553.5] "V"  PC,SBMU
 SG_ M2P_Current_B8_24 : 16|16@1+ (1,-20000) [-20000|45535] "A"  PC,SBMU
 SG_ M2P_PermitMaxCharge_I_B8_24 : 32|16@1+ (1,-20000) [-20000|45535] "A"  PC
 SG_ M2P_PermitMaxDisCharge_I_B8_24 : 48|16@1+ (1,-20000) [-20000|45535] "A"  PC

BO_ 2335829673 M2P_SUMDATA50__25: 8 MBMU
 SG_ M2P_Measure_Vol_B8_25 : 0|16@1+ (0.1,0) [0|6553.5] "V"  PC,SBMU
 SG_ M2P_Current_B8_25 : 16|16@1+ (1,-20000) [-20000|45535] "A"  PC,SBMU
 SG_ M2P_PermitMaxCharge_I_B8_25 : 32|16@1+ (1,-20000) [-20000|45535] "A"  PC
 SG_ M2P_PermitMaxDisCharge_I_B8_25 : 48|16@1+ (1,-20000) [-20000|45535] "A"  PC

BO_ 2335829674 M2P_SUMDATA50__26: 8 MBMU
 SG_ M2P_Measure_Vol_B8_26 : 0|16@1+ (0.1,0) [0|6553.5] "V"  PC,SBMU
 SG_ M2P_Current_B8_26 : 16|16@1+ (1,-20000) [-20000|45535] "A"  PC,SBMU
 SG_ M2P_PermitMaxCharge_I_B8_26 : 32|16@1+ (1,-20000) [-20000|45535] "A"  PC
 SG_ M2P_PermitMaxDisCharge_I_B8_26 : 48|16@1+ (1,-20000) [-20000|45535] "A"  PC

BO_ 2335829675 M2P_SUMDATA50__27: 8 MBMU
 SG_ M2P_Measure_Vol_B8_27 : 0|16@1+ (0.1,0) [0|6553.5] "V"  PC,SBMU
 SG_ M2P_Current_B8_27 : 16|16@1+ (1,-20000) [-20000|45535] "A"  PC,SBMU
 SG_ M2P_PermitMaxCharge_I_B8_27 : 32|16@1+ (1,-20000) [-20000|45535] "A"  PC
 SG_ M2P_PermitMaxDisCharge_I_B8_27 : 48|16@1+ (1,-20000) [-20000|45535] "A"  PC

BO_ 2335829676 M2P_SUMDATA50__28: 8 MBMU
 SG_ M2P_Measure_Vol_B8_28 : 0|16@1+ (0.1,0) [0|6553.5] "V"  PC,SBMU
 SG_ M2P_Current_B8_28 : 16|16@1+ (1,-20000) [-20000|45535] "A"  PC,SBMU
 SG_ M2P_PermitMaxCharge_I_B8_28 : 32|16@1+ (1,-20000) [-20000|45535] "A"  PC
 SG_ M2P_PermitMaxDisCharge_I_B8_28 : 48|16@1+ (1,-20000) [-20000|45535] "A"  PC

BO_ 2335829677 M2P_SUMDATA50__29: 8 MBMU
 SG_ M2P_Measure_Vol_B8_29 : 0|16@1+ (0.1,0) [0|6553.5] "V"  PC,SBMU
 SG_ M2P_Current_B8_29 : 16|16@1+ (1,-20000) [-20000|45535] "A"  PC,SBMU
 SG_ M2P_PermitMaxCharge_I_B8_29 : 32|16@1+ (1,-20000) [-20000|45535] "A"  PC
 SG_ M2P_PermitMaxDisCharge_I_B8_29 : 48|16@1+ (1,-20000) [-20000|45535] "A"  PC

BO_ 2335829678 M2P_SUMDATA50__30: 8 MBMU
 SG_ M2P_Measure_Vol_B8_30 : 0|16@1+ (0.1,0) [0|6553.5] "V"  PC,SBMU
 SG_ M2P_Current_B8_30 : 16|16@1+ (1,-20000) [-20000|45535] "A"  PC,SBMU
 SG_ M2P_PermitMaxCharge_I_B8_30 : 32|16@1+ (1,-20000) [-20000|45535] "A"  PC
 SG_ M2P_PermitMaxDisCharge_I_B8_30 : 48|16@1+ (1,-20000) [-20000|45535] "A"  PC

BO_ 2335829679 M2P_SUMDATA50__31: 8 MBMU
 SG_ M2P_Measure_Vol_B8_31 : 0|16@1+ (0.1,0) [0|6553.5] "V"  PC,SBMU
 SG_ M2P_Current_B8_31 : 16|16@1+ (1,-20000) [-20000|45535] "A"  PC,SBMU
 SG_ M2P_PermitMaxCharge_I_B8_31 : 32|16@1+ (1,-20000) [-20000|45535] "A"  PC
 SG_ M2P_PermitMaxDisCharge_I_B8_31 : 48|16@1+ (1,-20000) [-20000|45535] "A"  PC

BO_ 2335895185 M2P_SUMDATA51__01: 8 MBMU
 SG_ M2P_PermitMaxVolt_B8_01 : 0|16@1+ (0.1,0) [0|6553.5] "V"  PC
 SG_ M2P_PermitMinVolt_B8_01 : 16|16@1+ (0.1,0) [0|6553.5] "V"  PC
 SG_ M2P_PermitMaxPow_Chg_B8_01 : 32|16@1+ (1,-20000) [-20000|45535] "Kw"  PC
 SG_ M2P_PermitMaxPow_DisChg_B8_01 : 48|16@1+ (1,-20000) [-20000|45535] "Kw"  PC

BO_ 2335895186 M2P_SUMDATA51__02: 8 MBMU
 SG_ M2P_PermitMaxVolt_B8_02 : 0|16@1+ (0.1,0) [0|6553.5] "V"  PC
 SG_ M2P_PermitMinVolt_B8_02 : 16|16@1+ (0.1,0) [0|6553.5] "V"  PC
 SG_ M2P_PermitMaxPow_Chg_B8_02 : 32|16@1+ (1,-20000) [-20000|45535] "Kw"  PC
 SG_ M2P_PermitMaxPow_DisChg_B8_02 : 48|16@1+ (1,-20000) [-20000|45535] "Kw"  PC

BO_ 2335895187 M2P_SUMDATA51__03: 8 MBMU
 SG_ M2P_PermitMaxVolt_B8_03 : 0|16@1+ (0.1,0) [0|6553.5] "V"  PC
 SG_ M2P_PermitMinVolt_B8_03 : 16|16@1+ (0.1,0) [0|6553.5] "V"  PC
 SG_ M2P_PermitMaxPow_Chg_B8_03 : 32|16@1+ (1,-20000) [-20000|45535] "Kw"  PC
 SG_ M2P_PermitMaxPow_DisChg_B8_03 : 48|16@1+ (1,-20000) [-20000|45535] "Kw"  PC

BO_ 2335895188 M2P_SUMDATA51__04: 8 MBMU
 SG_ M2P_PermitMaxVolt_B8_04 : 0|16@1+ (0.1,0) [0|6553.5] "V"  PC
 SG_ M2P_PermitMinVolt_B8_04 : 16|16@1+ (0.1,0) [0|6553.5] "V"  PC
 SG_ M2P_PermitMaxPow_Chg_B8_04 : 32|16@1+ (1,-20000) [-20000|45535] "Kw"  PC
 SG_ M2P_PermitMaxPow_DisChg_B8_04 : 48|16@1+ (1,-20000) [-20000|45535] "Kw"  PC

BO_ 2335895189 M2P_SUMDATA51__05: 8 MBMU
 SG_ M2P_PermitMaxVolt_B8_05 : 0|16@1+ (0.1,0) [0|6553.5] "V"  PC
 SG_ M2P_PermitMinVolt_B8_05 : 16|16@1+ (0.1,0) [0|6553.5] "V"  PC
 SG_ M2P_PermitMaxPow_Chg_B8_05 : 32|16@1+ (1,-20000) [-20000|45535] "Kw"  PC
 SG_ M2P_PermitMaxPow_DisChg_B8_05 : 48|16@1+ (1,-20000) [-20000|45535] "Kw"  PC

BO_ 2335895190 M2P_SUMDATA51__06: 8 MBMU
 SG_ M2P_PermitMaxVolt_B8_06 : 0|16@1+ (0.1,0) [0|6553.5] "V"  PC
 SG_ M2P_PermitMinVolt_B8_06 : 16|16@1+ (0.1,0) [0|6553.5] "V"  PC
 SG_ M2P_PermitMaxPow_Chg_B8_06 : 32|16@1+ (1,-20000) [-20000|45535] "Kw"  PC
 SG_ M2P_PermitMaxPow_DisChg_B8_06 : 48|16@1+ (1,-20000) [-20000|45535] "Kw"  PC

BO_ 2335895191 M2P_SUMDATA51__07: 8 MBMU
 SG_ M2P_PermitMaxVolt_B8_07 : 0|16@1+ (0.1,0) [0|6553.5] "V"  PC
 SG_ M2P_PermitMinVolt_B8_07 : 16|16@1+ (0.1,0) [0|6553.5] "V"  PC
 SG_ M2P_PermitMaxPow_Chg_B8_07 : 32|16@1+ (1,-20000) [-20000|45535] "Kw"  PC
 SG_ M2P_PermitMaxPow_DisChg_B8_07 : 48|16@1+ (1,-20000) [-20000|45535] "Kw"  PC

BO_ 2335895192 M2P_SUMDATA51__08: 8 MBMU
 SG_ M2P_PermitMaxVolt_B8_08 : 0|16@1+ (0.1,0) [0|6553.5] "V"  PC
 SG_ M2P_PermitMinVolt_B8_08 : 16|16@1+ (0.1,0) [0|6553.5] "V"  PC
 SG_ M2P_PermitMaxPow_Chg_B8_08 : 32|16@1+ (1,-20000) [-20000|45535] "Kw"  PC
 SG_ M2P_PermitMaxPow_DisChg_B8_08 : 48|16@1+ (1,-20000) [-20000|45535] "Kw"  PC

BO_ 2335895193 M2P_SUMDATA51__09: 8 MBMU
 SG_ M2P_PermitMaxVolt_B8_09 : 0|16@1+ (0.1,0) [0|6553.5] "V"  PC
 SG_ M2P_PermitMinVolt_B8_09 : 16|16@1+ (0.1,0) [0|6553.5] "V"  PC
 SG_ M2P_PermitMaxPow_Chg_B8_09 : 32|16@1+ (1,-20000) [-20000|45535] "Kw"  PC
 SG_ M2P_PermitMaxPow_DisChg_B8_09 : 48|16@1+ (1,-20000) [-20000|45535] "Kw"  PC

BO_ 2335895194 M2P_SUMDATA51__10: 8 MBMU
 SG_ M2P_PermitMaxVolt_B8_10 : 0|16@1+ (0.1,0) [0|6553.5] "V"  PC
 SG_ M2P_PermitMinVolt_B8_10 : 16|16@1+ (0.1,0) [0|6553.5] "V"  PC
 SG_ M2P_PermitMaxPow_Chg_B8_10 : 32|16@1+ (1,-20000) [-20000|45535] "Kw"  PC
 SG_ M2P_PermitMaxPow_DisChg_B8_10 : 48|16@1+ (1,-20000) [-20000|45535] "Kw"  PC

BO_ 2335895195 M2P_SUMDATA51__11: 8 MBMU
 SG_ M2P_PermitMaxVolt_B8_11 : 0|16@1+ (0.1,0) [0|6553.5] "V"  PC
 SG_ M2P_PermitMinVolt_B8_11 : 16|16@1+ (0.1,0) [0|6553.5] "V"  PC
 SG_ M2P_PermitMaxPow_Chg_B8_11 : 32|16@1+ (1,-20000) [-20000|45535] "Kw"  PC
 SG_ M2P_PermitMaxPow_DisChg_B8_11 : 48|16@1+ (1,-20000) [-20000|45535] "Kw"  PC

BO_ 2335895196 M2P_SUMDATA51__12: 8 MBMU
 SG_ M2P_PermitMaxVolt_B8_12 : 0|16@1+ (0.1,0) [0|6553.5] "V"  PC
 SG_ M2P_PermitMinVolt_B8_12 : 16|16@1+ (0.1,0) [0|6553.5] "V"  PC
 SG_ M2P_PermitMaxPow_Chg_B8_12 : 32|16@1+ (1,-20000) [-20000|45535] "Kw"  PC
 SG_ M2P_PermitMaxPow_DisChg_B8_12 : 48|16@1+ (1,-20000) [-20000|45535] "Kw"  PC

BO_ 2335895197 M2P_SUMDATA51__13: 8 MBMU
 SG_ M2P_PermitMaxVolt_B8_13 : 0|16@1+ (0.1,0) [0|6553.5] "V"  PC
 SG_ M2P_PermitMinVolt_B8_13 : 16|16@1+ (0.1,0) [0|6553.5] "V"  PC
 SG_ M2P_PermitMaxPow_Chg_B8_13 : 32|16@1+ (1,-20000) [-20000|45535] "Kw"  PC
 SG_ M2P_PermitMaxPow_DisChg_B8_13 : 48|16@1+ (1,-20000) [-20000|45535] "Kw"  PC

BO_ 2335895198 M2P_SUMDATA51__14: 8 MBMU
 SG_ M2P_PermitMaxVolt_B8_14 : 0|16@1+ (0.1,0) [0|6553.5] "V"  PC
 SG_ M2P_PermitMinVolt_B8_14 : 16|16@1+ (0.1,0) [0|6553.5] "V"  PC
 SG_ M2P_PermitMaxPow_Chg_B8_14 : 32|16@1+ (1,-20000) [-20000|45535] "Kw"  PC
 SG_ M2P_PermitMaxPow_DisChg_B8_14 : 48|16@1+ (1,-20000) [-20000|45535] "Kw"  PC

BO_ 2335895199 M2P_SUMDATA51__15: 8 MBMU
 SG_ M2P_PermitMaxVolt_B8_15 : 0|16@1+ (0.1,0) [0|6553.5] "V"  PC
 SG_ M2P_PermitMinVolt_B8_15 : 16|16@1+ (0.1,0) [0|6553.5] "V"  PC
 SG_ M2P_PermitMaxPow_Chg_B8_15 : 32|16@1+ (1,-20000) [-20000|45535] "Kw"  PC
 SG_ M2P_PermitMaxPow_DisChg_B8_15 : 48|16@1+ (1,-20000) [-20000|45535] "Kw"  PC

BO_ 2335895200 M2P_SUMDATA51__16: 8 MBMU
 SG_ M2P_PermitMaxVolt_B8_16 : 0|16@1+ (0.1,0) [0|6553.5] "V"  PC
 SG_ M2P_PermitMinVolt_B8_16 : 16|16@1+ (0.1,0) [0|6553.5] "V"  PC
 SG_ M2P_PermitMaxPow_Chg_B8_16 : 32|16@1+ (1,-20000) [-20000|45535] "Kw"  PC
 SG_ M2P_PermitMaxPow_DisChg_B8_16 : 48|16@1+ (1,-20000) [-20000|45535] "Kw"  PC

CM_ SG_ 2335305382 M2P_Power_B6_22 "汇流排6实时功率";
CM_ SG_ 2335305382 M2P_SysremEngy_Chg_B6_22 "汇流排6充电剩余能量";
CM_ SG_ 2335305382 M2P_SysremEngy_DisChg_B6_22 "汇流排6放电剩余能量";
CM_ SG_ 2335305382 M2P_SysMaxVolt_B6_22 "汇流排6单体最大电压  ";
CM_ SG_ 2335305383 M2P_Power_B6_23 "汇流排6实时功率";
CM_ SG_ 2335305383 M2P_SysremEngy_Chg_B6_23 "汇流排6充电剩余能量";
CM_ SG_ 2335305383 M2P_SysremEngy_DisChg_B6_23 "汇流排6放电剩余能量";
CM_ SG_ 2335305383 M2P_SysMaxVolt_B6_23 "汇流排6单体最大电压  ";
CM_ SG_ 2335305384 M2P_Power_B6_24 "汇流排6实时功率";
CM_ SG_ 2335305384 M2P_SysremEngy_Chg_B6_24 "汇流排6充电剩余能量";
CM_ SG_ 2335305384 M2P_SysremEngy_DisChg_B6_24 "汇流排6放电剩余能量";
CM_ SG_ 2335305384 M2P_SysMaxVolt_B6_24 "汇流排6单体最大电压  ";
CM_ SG_ 2335305385 M2P_Power_B6_25 "汇流排6实时功率";
CM_ SG_ 2335305385 M2P_SysremEngy_Chg_B6_25 "汇流排6充电剩余能量";
CM_ SG_ 2335305385 M2P_SysremEngy_DisChg_B6_25 "汇流排6放电剩余能量";
CM_ SG_ 2335305385 M2P_SysMaxVolt_B6_25 "汇流排6单体最大电压  ";
CM_ SG_ 2335305386 M2P_Power_B6_26 "汇流排6实时功率";
CM_ SG_ 2335305386 M2P_SysremEngy_Chg_B6_26 "汇流排6充电剩余能量";
CM_ SG_ 2335305386 M2P_SysremEngy_DisChg_B6_26 "汇流排6放电剩余能量";
CM_ SG_ 2335305386 M2P_SysMaxVolt_B6_26 "汇流排6单体最大电压  ";
CM_ SG_ 2335305387 M2P_Power_B6_27 "汇流排6实时功率";
CM_ SG_ 2335305387 M2P_SysremEngy_Chg_B6_27 "汇流排6充电剩余能量";
CM_ SG_ 2335305387 M2P_SysremEngy_DisChg_B6_27 "汇流排6放电剩余能量";
CM_ SG_ 2335305387 M2P_SysMaxVolt_B6_27 "汇流排6单体最大电压  ";
CM_ SG_ 2335305388 M2P_Power_B6_28 "汇流排6实时功率";
CM_ SG_ 2335305388 M2P_SysremEngy_Chg_B6_28 "汇流排6充电剩余能量";
CM_ SG_ 2335305388 M2P_SysremEngy_DisChg_B6_28 "汇流排6放电剩余能量";
CM_ SG_ 2335305388 M2P_SysMaxVolt_B6_28 "汇流排6单体最大电压  ";
CM_ SG_ 2335305389 M2P_Power_B6_29 "汇流排6实时功率";
CM_ SG_ 2335305389 M2P_SysremEngy_Chg_B6_29 "汇流排6充电剩余能量";
CM_ SG_ 2335305389 M2P_SysremEngy_DisChg_B6_29 "汇流排6放电剩余能量";
CM_ SG_ 2335305389 M2P_SysMaxVolt_B6_29 "汇流排6单体最大电压  ";
CM_ SG_ 2335305390 M2P_Power_B6_30 "汇流排6实时功率";
CM_ SG_ 2335305390 M2P_SysremEngy_Chg_B6_30 "汇流排6充电剩余能量";
CM_ SG_ 2335305390 M2P_SysremEngy_DisChg_B6_30 "汇流排6放电剩余能量";
CM_ SG_ 2335305390 M2P_SysMaxVolt_B6_30 "汇流排6单体最大电压  ";
CM_ SG_ 2335305391 M2P_Power_B6_31 "汇流排6实时功率";
CM_ SG_ 2335305391 M2P_SysremEngy_Chg_B6_31 "汇流排6充电剩余能量";
CM_ SG_ 2335305391 M2P_SysremEngy_DisChg_B6_31 "汇流排6放电剩余能量";
CM_ SG_ 2335305391 M2P_SysMaxVolt_B6_31 "汇流排6单体最大电压  ";
CM_ SG_ 2335370897 M2P_SysMinVolt_B6_01 "汇流排6单体最小电压";
CM_ SG_ 2335370897 M2P_SysAvgVolt_B6_01 "汇流排6单体平均电压";
CM_ SG_ 2335370897 M2P_BMS_Status_B6 "汇流排6能量状态";
CM_ SG_ 2335370897 M2P_SOC_B6 "汇流排6系统SOC";
CM_ SG_ 2335370897 M2P_SOH_B6 "汇流排6系统SOH";
CM_ SG_ 2335370897 Reserved_01 "预留";
CM_ SG_ 2335370898 M2P_SysMinVolt_B6_02 "汇流排6单体最小电压";
CM_ SG_ 2335370898 M2P_SysAvgVolt_B6_02 "汇流排6单体平均电压";
CM_ SG_ 2335370898 M2P_BMS_Status_B6 "汇流排6能量状态";
CM_ SG_ 2335370898 M2P_SOC_B6 "汇流排6系统SOC";
CM_ SG_ 2335370898 M2P_SOH_B6 "汇流排6系统SOH";
CM_ SG_ 2335370898 Reserved_02 "预留";
CM_ SG_ 2335370899 M2P_SysMinVolt_B6_03 "汇流排6单体最小电压";
CM_ SG_ 2335370899 M2P_SysAvgVolt_B6_03 "汇流排6单体平均电压";
CM_ SG_ 2335370899 M2P_BMS_Status_B6 "汇流排6能量状态";
CM_ SG_ 2335370899 M2P_SOC_B6 "汇流排6系统SOC";
CM_ SG_ 2335370899 M2P_SOH_B6 "汇流排6系统SOH";
CM_ SG_ 2335370899 Reserved_03 "预留";
CM_ SG_ 2335370900 M2P_SysMinVolt_B6_04 "汇流排6单体最小电压";
CM_ SG_ 2335370900 M2P_SysAvgVolt_B6_04 "汇流排6单体平均电压";
CM_ SG_ 2335370900 M2P_BMS_Status_B6 "汇流排6能量状态";
CM_ SG_ 2335370900 M2P_SOC_B6 "汇流排6系统SOC";
CM_ SG_ 2335370900 M2P_SOH_B6 "汇流排6系统SOH";
CM_ SG_ 2335370900 Reserved_04 "预留";
CM_ SG_ 2335370901 M2P_SysMinVolt_B6_05 "汇流排6单体最小电压";
CM_ SG_ 2335370901 M2P_SysAvgVolt_B6_05 "汇流排6单体平均电压";
CM_ SG_ 2335370901 M2P_BMS_Status_B6 "汇流排6能量状态";
CM_ SG_ 2335370901 M2P_SOC_B6 "汇流排6系统SOC";
CM_ SG_ 2335370901 M2P_SOH_B6 "汇流排6系统SOH";
CM_ SG_ 2335370901 Reserved_05 "预留";
CM_ SG_ 2335370902 M2P_SysMinVolt_B6_06 "汇流排6单体最小电压";
CM_ SG_ 2335370902 M2P_SysAvgVolt_B6_06 "汇流排6单体平均电压";
CM_ SG_ 2335370902 M2P_BMS_Status_B6 "汇流排6能量状态";
CM_ SG_ 2335370902 M2P_SOC_B6 "汇流排6系统SOC";
CM_ SG_ 2335370902 M2P_SOH_B6 "汇流排6系统SOH";
CM_ SG_ 2335370902 Reserved_06 "预留";
CM_ SG_ 2335370903 M2P_SysMinVolt_B6_07 "汇流排6单体最小电压";
CM_ SG_ 2335370903 M2P_SysAvgVolt_B6_07 "汇流排6单体平均电压";
CM_ SG_ 2335370903 M2P_BMS_Status_B6 "汇流排6能量状态";
CM_ SG_ 2335370903 M2P_SOC_B6 "汇流排6系统SOC";
CM_ SG_ 2335370903 M2P_SOH_B6 "汇流排6系统SOH";
CM_ SG_ 2335370903 Reserved_07 "预留";
CM_ SG_ 2335370904 M2P_SysMinVolt_B6_08 "汇流排6单体最小电压";
CM_ SG_ 2335370904 M2P_SysAvgVolt_B6_08 "汇流排6单体平均电压";
CM_ SG_ 2335370904 M2P_BMS_Status_B6 "汇流排6能量状态";
CM_ SG_ 2335370904 M2P_SOC_B6 "汇流排6系统SOC";
CM_ SG_ 2335370904 M2P_SOH_B6 "汇流排6系统SOH";
CM_ SG_ 2335370904 Reserved_08 "预留";
CM_ SG_ 2335370905 M2P_SysMinVolt_B6_09 "汇流排6单体最小电压";
CM_ SG_ 2335370905 M2P_SysAvgVolt_B6_09 "汇流排6单体平均电压";
CM_ SG_ 2335370905 M2P_BMS_Status_B6 "汇流排6能量状态";
CM_ SG_ 2335370905 M2P_SOC_B6 "汇流排6系统SOC";
CM_ SG_ 2335370905 M2P_SOH_B6 "汇流排6系统SOH";
CM_ SG_ 2335370905 Reserved_09 "预留";
CM_ SG_ 2335370906 M2P_SysMinVolt_B6_10 "汇流排6单体最小电压";
CM_ SG_ 2335370906 M2P_SysAvgVolt_B6_10 "汇流排6单体平均电压";
CM_ SG_ 2335370906 M2P_BMS_Status_B6 "汇流排6能量状态";
CM_ SG_ 2335370906 M2P_SOC_B6 "汇流排6系统SOC";
CM_ SG_ 2335370906 M2P_SOH_B6 "汇流排6系统SOH";
CM_ SG_ 2335370906 Reserved_10 "预留";
CM_ SG_ 2335370907 M2P_SysMinVolt_B6_11 "汇流排6单体最小电压";
CM_ SG_ 2335370907 M2P_SysAvgVolt_B6_11 "汇流排6单体平均电压";
CM_ SG_ 2335370907 M2P_BMS_Status_B6 "汇流排6能量状态";
CM_ SG_ 2335370907 M2P_SOC_B6 "汇流排6系统SOC";
CM_ SG_ 2335370907 M2P_SOH_B6 "汇流排6系统SOH";
CM_ SG_ 2335370907 Reserved_11 "预留";
CM_ SG_ 2335370908 M2P_SysMinVolt_B6_12 "汇流排6单体最小电压";
CM_ SG_ 2335370908 M2P_SysAvgVolt_B6_12 "汇流排6单体平均电压";
CM_ SG_ 2335370908 M2P_BMS_Status_B6 "汇流排6能量状态";
CM_ SG_ 2335370908 M2P_SOC_B6 "汇流排6系统SOC";
CM_ SG_ 2335370908 M2P_SOH_B6 "汇流排6系统SOH";
CM_ SG_ 2335370908 Reserved_12 "预留";
CM_ SG_ 2335370909 M2P_SysMinVolt_B6_13 "汇流排6单体最小电压";
CM_ SG_ 2335370909 M2P_SysAvgVolt_B6_13 "汇流排6单体平均电压";
CM_ SG_ 2335370909 M2P_BMS_Status_B6 "汇流排6能量状态";
CM_ SG_ 2335370909 M2P_SOC_B6 "汇流排6系统SOC";
CM_ SG_ 2335370909 M2P_SOH_B6 "汇流排6系统SOH";
CM_ SG_ 2335370909 Reserved_13 "预留";
CM_ SG_ 2335370910 M2P_SysMinVolt_B6_14 "汇流排6单体最小电压";
CM_ SG_ 2335370910 M2P_SysAvgVolt_B6_14 "汇流排6单体平均电压";
CM_ SG_ 2335370910 M2P_BMS_Status_B6 "汇流排6能量状态";
CM_ SG_ 2335370910 M2P_SOC_B6 "汇流排6系统SOC";
CM_ SG_ 2335370910 M2P_SOH_B6 "汇流排6系统SOH";
CM_ SG_ 2335370910 Reserved_14 "预留";
CM_ SG_ 2335370911 M2P_SysMinVolt_B6_15 "汇流排6单体最小电压";
CM_ SG_ 2335370911 M2P_SysAvgVolt_B6_15 "汇流排6单体平均电压";
CM_ SG_ 2335370911 M2P_BMS_Status_B6 "汇流排6能量状态";
CM_ SG_ 2335370911 M2P_SOC_B6 "汇流排6系统SOC";
CM_ SG_ 2335370911 M2P_SOH_B6 "汇流排6系统SOH";
CM_ SG_ 2335370911 Reserved_15 "预留";
CM_ SG_ 2335370912 M2P_SysMinVolt_B6_16 "汇流排6单体最小电压";
CM_ SG_ 2335370912 M2P_SysAvgVolt_B6_16 "汇流排6单体平均电压";
CM_ SG_ 2335370912 M2P_BMS_Status_B6 "汇流排6能量状态";
CM_ SG_ 2335370912 M2P_SOC_B6 "汇流排6系统SOC";
CM_ SG_ 2335370912 M2P_SOH_B6 "汇流排6系统SOH";
CM_ SG_ 2335370912 Reserved_16 "预留";
CM_ SG_ 2335370913 M2P_SysMinVolt_B6_17 "汇流排6单体最小电压";
CM_ SG_ 2335370913 M2P_SysAvgVolt_B6_17 "汇流排6单体平均电压";
CM_ SG_ 2335370913 M2P_BMS_Status_B6 "汇流排6能量状态";
CM_ SG_ 2335370913 M2P_SOC_B6 "汇流排6系统SOC";
CM_ SG_ 2335370913 M2P_SOH_B6 "汇流排6系统SOH";
CM_ SG_ 2335370913 Reserved_17 "预留";
CM_ SG_ 2335370914 M2P_SysMinVolt_B6_18 "汇流排6单体最小电压";
CM_ SG_ 2335370914 M2P_SysAvgVolt_B6_18 "汇流排6单体平均电压";
CM_ SG_ 2335370914 M2P_BMS_Status_B6 "汇流排6能量状态";
CM_ SG_ 2335370914 M2P_SOC_B6 "汇流排6系统SOC";
CM_ SG_ 2335370914 M2P_SOH_B6 "汇流排6系统SOH";
CM_ SG_ 2335370914 Reserved_18 "预留";
CM_ SG_ 2335370915 M2P_SysMinVolt_B6_19 "汇流排6单体最小电压";
CM_ SG_ 2335370915 M2P_SysAvgVolt_B6_19 "汇流排6单体平均电压";
CM_ SG_ 2335370915 M2P_BMS_Status_B6 "汇流排6能量状态";
CM_ SG_ 2335370915 M2P_SOC_B6 "汇流排6系统SOC";
CM_ SG_ 2335370915 M2P_SOH_B6 "汇流排6系统SOH";
CM_ SG_ 2335370915 Reserved_19 "预留";
CM_ SG_ 2335370916 M2P_SysMinVolt_B6_20 "汇流排6单体最小电压";
CM_ SG_ 2335370916 M2P_SysAvgVolt_B6_20 "汇流排6单体平均电压";
CM_ SG_ 2335370916 M2P_BMS_Status_B6 "汇流排6能量状态";
CM_ SG_ 2335370916 M2P_SOC_B6 "汇流排6系统SOC";
CM_ SG_ 2335370916 M2P_SOH_B6 "汇流排6系统SOH";
CM_ SG_ 2335370916 Reserved_20 "预留";
CM_ SG_ 2335370917 M2P_SysMinVolt_B6_21 "汇流排6单体最小电压";
CM_ SG_ 2335370917 M2P_SysAvgVolt_B6_21 "汇流排6单体平均电压";
CM_ SG_ 2335370917 M2P_BMS_Status_B6 "汇流排6能量状态";
CM_ SG_ 2335370917 M2P_SOC_B6 "汇流排6系统SOC";
CM_ SG_ 2335370917 M2P_SOH_B6 "汇流排6系统SOH";
CM_ SG_ 2335370917 Reserved_21 "预留";
CM_ SG_ 2335370918 M2P_SysMinVolt_B6_22 "汇流排6单体最小电压";
CM_ SG_ 2335370918 M2P_SysAvgVolt_B6_22 "汇流排6单体平均电压";
CM_ SG_ 2335370918 M2P_BMS_Status_B6 "汇流排6能量状态";
CM_ SG_ 2335370918 M2P_SOC_B6 "汇流排6系统SOC";
CM_ SG_ 2335370918 M2P_SOH_B6 "汇流排6系统SOH";
CM_ SG_ 2335370918 Reserved_22 "预留";
CM_ SG_ 2335370919 M2P_SysMinVolt_B6_23 "汇流排6单体最小电压";
CM_ SG_ 2335370919 M2P_SysAvgVolt_B6_23 "汇流排6单体平均电压";
CM_ SG_ 2335370919 M2P_BMS_Status_B6 "汇流排6能量状态";
CM_ SG_ 2335370919 M2P_SOC_B6 "汇流排6系统SOC";
CM_ SG_ 2335370919 M2P_SOH_B6 "汇流排6系统SOH";
CM_ SG_ 2335370919 Reserved_23 "预留";
CM_ SG_ 2335370920 M2P_SysMinVolt_B6_24 "汇流排6单体最小电压";
CM_ SG_ 2335370920 M2P_SysAvgVolt_B6_24 "汇流排6单体平均电压";
CM_ SG_ 2335370920 M2P_BMS_Status_B6 "汇流排6能量状态";
CM_ SG_ 2335370920 M2P_SOC_B6 "汇流排6系统SOC";
CM_ SG_ 2335370920 M2P_SOH_B6 "汇流排6系统SOH";
CM_ SG_ 2335370920 Reserved_24 "预留";
CM_ SG_ 2335370921 M2P_SysMinVolt_B6_25 "汇流排6单体最小电压";
CM_ SG_ 2335370921 M2P_SysAvgVolt_B6_25 "汇流排6单体平均电压";
CM_ SG_ 2335370921 M2P_BMS_Status_B6 "汇流排6能量状态";
CM_ SG_ 2335370921 M2P_SOC_B6 "汇流排6系统SOC";
CM_ SG_ 2335370921 M2P_SOH_B6 "汇流排6系统SOH";
CM_ SG_ 2335370921 Reserved_25 "预留";
CM_ SG_ 2335370922 M2P_SysMinVolt_B6_26 "汇流排6单体最小电压";
CM_ SG_ 2335370922 M2P_SysAvgVolt_B6_26 "汇流排6单体平均电压";
CM_ SG_ 2335370922 M2P_BMS_Status_B6 "汇流排6能量状态";
CM_ SG_ 2335370922 M2P_SOC_B6 "汇流排6系统SOC";
CM_ SG_ 2335370922 M2P_SOH_B6 "汇流排6系统SOH";
CM_ SG_ 2335370922 Reserved_26 "预留";
CM_ SG_ 2335370923 M2P_SysMinVolt_B6_27 "汇流排6单体最小电压";
CM_ SG_ 2335370923 M2P_SysAvgVolt_B6_27 "汇流排6单体平均电压";
CM_ SG_ 2335370923 M2P_BMS_Status_B6 "汇流排6能量状态";
CM_ SG_ 2335370923 M2P_SOC_B6 "汇流排6系统SOC";
CM_ SG_ 2335370923 M2P_SOH_B6 "汇流排6系统SOH";
CM_ SG_ 2335370923 Reserved_27 "预留";
CM_ SG_ 2335370924 M2P_SysMinVolt_B6_28 "汇流排6单体最小电压";
CM_ SG_ 2335370924 M2P_SysAvgVolt_B6_28 "汇流排6单体平均电压";
CM_ SG_ 2335370924 M2P_BMS_Status_B6 "汇流排6能量状态";
CM_ SG_ 2335370924 M2P_SOC_B6 "汇流排6系统SOC";
CM_ SG_ 2335370924 M2P_SOH_B6 "汇流排6系统SOH";
CM_ SG_ 2335370924 Reserved_28 "预留";
CM_ SG_ 2335370925 M2P_SysMinVolt_B6_29 "汇流排6单体最小电压";
CM_ SG_ 2335370925 M2P_SysAvgVolt_B6_29 "汇流排6单体平均电压";
CM_ SG_ 2335370925 M2P_BMS_Status_B6 "汇流排6能量状态";
CM_ SG_ 2335370925 M2P_SOC_B6 "汇流排6系统SOC";
CM_ SG_ 2335370925 M2P_SOH_B6 "汇流排6系统SOH";
CM_ SG_ 2335370925 Reserved_29 "预留";
CM_ SG_ 2335370926 M2P_SysMinVolt_B6_30 "汇流排6单体最小电压";
CM_ SG_ 2335370926 M2P_SysAvgVolt_B6_30 "汇流排6单体平均电压";
CM_ SG_ 2335370926 M2P_BMS_Status_B6 "汇流排6能量状态";
CM_ SG_ 2335370926 M2P_SOC_B6 "汇流排6系统SOC";
CM_ SG_ 2335370926 M2P_SOH_B6 "汇流排6系统SOH";
CM_ SG_ 2335370926 Reserved_30 "预留";
CM_ SG_ 2335370927 M2P_SysMinVolt_B6_31 "汇流排6单体最小电压";
CM_ SG_ 2335370927 M2P_SysAvgVolt_B6_31 "汇流排6单体平均电压";
CM_ SG_ 2335370927 M2P_BMS_Status_B6 "汇流排6能量状态";
CM_ SG_ 2335370927 M2P_SOC_B6 "汇流排6系统SOC";
CM_ SG_ 2335370927 M2P_SOH_B6 "汇流排6系统SOH";
CM_ SG_ 2335370927 Reserved_31 "预留";
CM_ SG_ 2335436433 M2P_SOE_Charge_B6 "汇流排5系可充电SOE";
CM_ SG_ 2335436433 M2P_SOE_Discharge_B6 "汇流排5系可放电SOE";
CM_ SG_ 2335436433 Reserved_01 "预留";
CM_ SG_ 2335436434 M2P_SOE_Charge_B6 "汇流排5系可充电SOE";
CM_ SG_ 2335436434 M2P_SOE_Discharge_B6 "汇流排5系可放电SOE";
CM_ SG_ 2335436434 Reserved_02 "预留";
CM_ SG_ 2335436435 M2P_SOE_Charge_B6 "汇流排5系可充电SOE";
CM_ SG_ 2335436435 M2P_SOE_Discharge_B6 "汇流排5系可放电SOE";
CM_ SG_ 2335436435 Reserved_03 "预留";
CM_ SG_ 2335436436 M2P_SOE_Charge_B6 "汇流排5系可充电SOE";
CM_ SG_ 2335436436 M2P_SOE_Discharge_B6 "汇流排5系可放电SOE";
CM_ SG_ 2335436436 Reserved_04 "预留";
CM_ SG_ 2335436437 M2P_SOE_Charge_B6 "汇流排5系可充电SOE";
CM_ SG_ 2335436437 M2P_SOE_Discharge_B6 "汇流排5系可放电SOE";
CM_ SG_ 2335436437 Reserved_05 "预留";
CM_ SG_ 2335436438 M2P_SOE_Charge_B6 "汇流排5系可充电SOE";
CM_ SG_ 2335436438 M2P_SOE_Discharge_B6 "汇流排5系可放电SOE";
CM_ SG_ 2335436438 Reserved_06 "预留";
CM_ SG_ 2335436439 M2P_SOE_Charge_B6 "汇流排5系可充电SOE";
CM_ SG_ 2335436439 M2P_SOE_Discharge_B6 "汇流排5系可放电SOE";
CM_ SG_ 2335436439 Reserved_07 "预留";
CM_ SG_ 2335436440 M2P_SOE_Charge_B6 "汇流排5系可充电SOE";
CM_ SG_ 2335436440 M2P_SOE_Discharge_B6 "汇流排5系可放电SOE";
CM_ SG_ 2335436440 Reserved_08 "预留";
CM_ SG_ 2335436441 M2P_SOE_Charge_B6 "汇流排5系可充电SOE";
CM_ SG_ 2335436441 M2P_SOE_Discharge_B6 "汇流排5系可放电SOE";
CM_ SG_ 2335436441 Reserved_09 "预留";
CM_ SG_ 2335436442 M2P_SOE_Charge_B6 "汇流排5系可充电SOE";
CM_ SG_ 2335436442 M2P_SOE_Discharge_B6 "汇流排5系可放电SOE";
CM_ SG_ 2335436442 Reserved_10 "预留";
CM_ SG_ 2335436443 M2P_SOE_Charge_B6 "汇流排5系可充电SOE";
CM_ SG_ 2335436443 M2P_SOE_Discharge_B6 "汇流排5系可放电SOE";
CM_ SG_ 2335436443 Reserved_11 "预留";
CM_ SG_ 2335436444 M2P_SOE_Charge_B6 "汇流排5系可充电SOE";
CM_ SG_ 2335436444 M2P_SOE_Discharge_B6 "汇流排5系可放电SOE";
CM_ SG_ 2335436444 Reserved_12 "预留";
CM_ SG_ 2335436445 M2P_SOE_Charge_B6 "汇流排5系可充电SOE";
CM_ SG_ 2335436445 M2P_SOE_Discharge_B6 "汇流排5系可放电SOE";
CM_ SG_ 2335436445 Reserved_13 "预留";
CM_ SG_ 2335436446 M2P_SOE_Charge_B6 "汇流排5系可充电SOE";
CM_ SG_ 2335436446 M2P_SOE_Discharge_B6 "汇流排5系可放电SOE";
CM_ SG_ 2335436446 Reserved_14 "预留";
CM_ SG_ 2335436447 M2P_SOE_Charge_B6 "汇流排5系可充电SOE";
CM_ SG_ 2335436447 M2P_SOE_Discharge_B6 "汇流排5系可放电SOE";
CM_ SG_ 2335436447 Reserved_15 "预留";
CM_ SG_ 2335436448 M2P_SOE_Charge_B6 "汇流排5系可充电SOE";
CM_ SG_ 2335436448 M2P_SOE_Discharge_B6 "汇流排5系可放电SOE";
CM_ SG_ 2335436448 Reserved_16 "预留";
CM_ SG_ 2335436449 M2P_SOE_Charge_B6 "汇流排5系可充电SOE";
CM_ SG_ 2335436449 M2P_SOE_Discharge_B6 "汇流排5系可放电SOE";
CM_ SG_ 2335436449 Reserved_17 "预留";
CM_ SG_ 2335436450 M2P_SOE_Charge_B6 "汇流排5系可充电SOE";
CM_ SG_ 2335436450 M2P_SOE_Discharge_B6 "汇流排5系可放电SOE";
CM_ SG_ 2335436450 Reserved_18 "预留";
CM_ SG_ 2335436451 M2P_SOE_Charge_B6 "汇流排5系可充电SOE";
CM_ SG_ 2335436451 M2P_SOE_Discharge_B6 "汇流排5系可放电SOE";
CM_ SG_ 2335436451 Reserved_19 "预留";
CM_ SG_ 2335436452 M2P_SOE_Charge_B6 "汇流排5系可充电SOE";
CM_ SG_ 2335436452 M2P_SOE_Discharge_B6 "汇流排5系可放电SOE";
CM_ SG_ 2335436452 Reserved_20 "预留";
CM_ SG_ 2335436453 M2P_SOE_Charge_B6 "汇流排5系可充电SOE";
CM_ SG_ 2335436453 M2P_SOE_Discharge_B6 "汇流排5系可放电SOE";
CM_ SG_ 2335436453 Reserved_21 "预留";
CM_ SG_ 2335436454 M2P_SOE_Charge_B6 "汇流排5系可充电SOE";
CM_ SG_ 2335436454 M2P_SOE_Discharge_B6 "汇流排5系可放电SOE";
CM_ SG_ 2335436454 Reserved_22 "预留";
CM_ SG_ 2335436455 M2P_SOE_Charge_B6 "汇流排5系可充电SOE";
CM_ SG_ 2335436455 M2P_SOE_Discharge_B6 "汇流排5系可放电SOE";
CM_ SG_ 2335436455 Reserved_23 "预留";
CM_ SG_ 2335436456 M2P_SOE_Charge_B6 "汇流排5系可充电SOE";
CM_ SG_ 2335436456 M2P_SOE_Discharge_B6 "汇流排5系可放电SOE";
CM_ SG_ 2335436456 Reserved_24 "预留";
CM_ SG_ 2335436457 M2P_SOE_Charge_B6 "汇流排5系可充电SOE";
CM_ SG_ 2335436457 M2P_SOE_Discharge_B6 "汇流排5系可放电SOE";
CM_ SG_ 2335436457 Reserved_25 "预留";
CM_ SG_ 2335436458 M2P_SOE_Charge_B6 "汇流排5系可充电SOE";
CM_ SG_ 2335436458 M2P_SOE_Discharge_B6 "汇流排5系可放电SOE";
CM_ SG_ 2335436458 Reserved_26 "预留";
CM_ SG_ 2335436459 M2P_SOE_Charge_B6 "汇流排5系可充电SOE";
CM_ SG_ 2335436459 M2P_SOE_Discharge_B6 "汇流排5系可放电SOE";
CM_ SG_ 2335436459 Reserved_27 "预留";
CM_ SG_ 2335436460 M2P_SOE_Charge_B6 "汇流排5系可充电SOE";
CM_ SG_ 2335436460 M2P_SOE_Discharge_B6 "汇流排5系可放电SOE";
CM_ SG_ 2335436460 Reserved_28 "预留";
CM_ SG_ 2335436461 M2P_SOE_Charge_B6 "汇流排5系可充电SOE";
CM_ SG_ 2335436461 M2P_SOE_Discharge_B6 "汇流排5系可放电SOE";
CM_ SG_ 2335436461 Reserved_29 "预留";
CM_ SG_ 2335436462 M2P_SOE_Charge_B6 "汇流排5系可充电SOE";
CM_ SG_ 2335436462 M2P_SOE_Discharge_B6 "汇流排5系可放电SOE";
CM_ SG_ 2335436462 Reserved_30 "预留";
CM_ SG_ 2335436463 M2P_SOE_Charge_B6 "汇流排5系可充电SOE";
CM_ SG_ 2335436463 M2P_SOE_Discharge_B6 "汇流排5系可放电SOE";
CM_ SG_ 2335436463 Reserved_31 "预留";
CM_ SG_ 2335501969 M2P_Measure_Vol_B7_01 "汇流排7所有高压在线电柜外侧电压平均值    ";
CM_ SG_ 2335501969 M2P_Current_B7_01 "汇流排7所有电柜电流累加和";
CM_ SG_ 2335501969 M2P_PermitMaxCharge_I_B7_01 "汇流排7最大允许充电电流";
CM_ SG_ 2335501969 M2P_PermitMaxDisCharge_I_B7_01 "汇流排7最大允许放电电流";
CM_ SG_ 2335501970 M2P_Measure_Vol_B7_02 "汇流排7所有高压在线电柜外侧电压平均值    ";
CM_ SG_ 2335501970 M2P_Current_B7_02 "汇流排7所有电柜电流累加和";
CM_ SG_ 2335501970 M2P_PermitMaxCharge_I_B7_02 "汇流排7最大允许充电电流";
CM_ SG_ 2335501970 M2P_PermitMaxDisCharge_I_B7_02 "汇流排7最大允许放电电流";
CM_ SG_ 2335501971 M2P_Measure_Vol_B7_03 "汇流排7所有高压在线电柜外侧电压平均值    ";
CM_ SG_ 2335501971 M2P_Current_B7_03 "汇流排7所有电柜电流累加和";
CM_ SG_ 2335501971 M2P_PermitMaxCharge_I_B7_03 "汇流排7最大允许充电电流";
CM_ SG_ 2335501971 M2P_PermitMaxDisCharge_I_B7_03 "汇流排7最大允许放电电流";
CM_ SG_ 2335501972 M2P_Measure_Vol_B7_04 "汇流排7所有高压在线电柜外侧电压平均值    ";
CM_ SG_ 2335501972 M2P_Current_B7_04 "汇流排7所有电柜电流累加和";
CM_ SG_ 2335501972 M2P_PermitMaxCharge_I_B7_04 "汇流排7最大允许充电电流";
CM_ SG_ 2335501972 M2P_PermitMaxDisCharge_I_B7_04 "汇流排7最大允许放电电流";
CM_ SG_ 2335501973 M2P_Measure_Vol_B7_05 "汇流排7所有高压在线电柜外侧电压平均值    ";
CM_ SG_ 2335501973 M2P_Current_B7_05 "汇流排7所有电柜电流累加和";
CM_ SG_ 2335501973 M2P_PermitMaxCharge_I_B7_05 "汇流排7最大允许充电电流";
CM_ SG_ 2335501973 M2P_PermitMaxDisCharge_I_B7_05 "汇流排7最大允许放电电流";
CM_ SG_ 2335501974 M2P_Measure_Vol_B7_06 "汇流排7所有高压在线电柜外侧电压平均值    ";
CM_ SG_ 2335501974 M2P_Current_B7_06 "汇流排7所有电柜电流累加和";
CM_ SG_ 2335501974 M2P_PermitMaxCharge_I_B7_06 "汇流排7最大允许充电电流";
CM_ SG_ 2335501974 M2P_PermitMaxDisCharge_I_B7_06 "汇流排7最大允许放电电流";
CM_ SG_ 2335501975 M2P_Measure_Vol_B7_07 "汇流排7所有高压在线电柜外侧电压平均值    ";
CM_ SG_ 2335501975 M2P_Current_B7_07 "汇流排7所有电柜电流累加和";
CM_ SG_ 2335501975 M2P_PermitMaxCharge_I_B7_07 "汇流排7最大允许充电电流";
CM_ SG_ 2335501975 M2P_PermitMaxDisCharge_I_B7_07 "汇流排7最大允许放电电流";
CM_ SG_ 2335501976 M2P_Measure_Vol_B7_08 "汇流排7所有高压在线电柜外侧电压平均值    ";
CM_ SG_ 2335501976 M2P_Current_B7_08 "汇流排7所有电柜电流累加和";
CM_ SG_ 2335501976 M2P_PermitMaxCharge_I_B7_08 "汇流排7最大允许充电电流";
CM_ SG_ 2335501976 M2P_PermitMaxDisCharge_I_B7_08 "汇流排7最大允许放电电流";
CM_ SG_ 2335501977 M2P_Measure_Vol_B7_09 "汇流排7所有高压在线电柜外侧电压平均值    ";
CM_ SG_ 2335501977 M2P_Current_B7_09 "汇流排7所有电柜电流累加和";
CM_ SG_ 2335501977 M2P_PermitMaxCharge_I_B7_09 "汇流排7最大允许充电电流";
CM_ SG_ 2335501977 M2P_PermitMaxDisCharge_I_B7_09 "汇流排7最大允许放电电流";
CM_ SG_ 2335501978 M2P_Measure_Vol_B7_10 "汇流排7所有高压在线电柜外侧电压平均值    ";
CM_ SG_ 2335501978 M2P_Current_B7_10 "汇流排7所有电柜电流累加和";
CM_ SG_ 2335501978 M2P_PermitMaxCharge_I_B7_10 "汇流排7最大允许充电电流";
CM_ SG_ 2335501978 M2P_PermitMaxDisCharge_I_B7_10 "汇流排7最大允许放电电流";
CM_ SG_ 2335501979 M2P_Measure_Vol_B7_11 "汇流排7所有高压在线电柜外侧电压平均值    ";
CM_ SG_ 2335501979 M2P_Current_B7_11 "汇流排7所有电柜电流累加和";
CM_ SG_ 2335501979 M2P_PermitMaxCharge_I_B7_11 "汇流排7最大允许充电电流";
CM_ SG_ 2335501979 M2P_PermitMaxDisCharge_I_B7_11 "汇流排7最大允许放电电流";
CM_ SG_ 2335501980 M2P_Measure_Vol_B7_12 "汇流排7所有高压在线电柜外侧电压平均值    ";
CM_ SG_ 2335501980 M2P_Current_B7_12 "汇流排7所有电柜电流累加和";
CM_ SG_ 2335501980 M2P_PermitMaxCharge_I_B7_12 "汇流排7最大允许充电电流";
CM_ SG_ 2335501980 M2P_PermitMaxDisCharge_I_B7_12 "汇流排7最大允许放电电流";
CM_ SG_ 2335501981 M2P_Measure_Vol_B7_13 "汇流排7所有高压在线电柜外侧电压平均值    ";
CM_ SG_ 2335501981 M2P_Current_B7_13 "汇流排7所有电柜电流累加和";
CM_ SG_ 2335501981 M2P_PermitMaxCharge_I_B7_13 "汇流排7最大允许充电电流";
CM_ SG_ 2335501981 M2P_PermitMaxDisCharge_I_B7_13 "汇流排7最大允许放电电流";
CM_ SG_ 2335501982 M2P_Measure_Vol_B7_14 "汇流排7所有高压在线电柜外侧电压平均值    ";
CM_ SG_ 2335501982 M2P_Current_B7_14 "汇流排7所有电柜电流累加和";
CM_ SG_ 2335501982 M2P_PermitMaxCharge_I_B7_14 "汇流排7最大允许充电电流";
CM_ SG_ 2335501982 M2P_PermitMaxDisCharge_I_B7_14 "汇流排7最大允许放电电流";
CM_ SG_ 2335501983 M2P_Measure_Vol_B7_15 "汇流排7所有高压在线电柜外侧电压平均值    ";
CM_ SG_ 2335501983 M2P_Current_B7_15 "汇流排7所有电柜电流累加和";
CM_ SG_ 2335501983 M2P_PermitMaxCharge_I_B7_15 "汇流排7最大允许充电电流";
CM_ SG_ 2335501983 M2P_PermitMaxDisCharge_I_B7_15 "汇流排7最大允许放电电流";
CM_ SG_ 2335501984 M2P_Measure_Vol_B7_16 "汇流排7所有高压在线电柜外侧电压平均值    ";
CM_ SG_ 2335501984 M2P_Current_B7_16 "汇流排7所有电柜电流累加和";
CM_ SG_ 2335501984 M2P_PermitMaxCharge_I_B7_16 "汇流排7最大允许充电电流";
CM_ SG_ 2335501984 M2P_PermitMaxDisCharge_I_B7_16 "汇流排7最大允许放电电流";
CM_ SG_ 2335501985 M2P_Measure_Vol_B7_17 "汇流排7所有高压在线电柜外侧电压平均值    ";
CM_ SG_ 2335501985 M2P_Current_B7_17 "汇流排7所有电柜电流累加和";
CM_ SG_ 2335501985 M2P_PermitMaxCharge_I_B7_17 "汇流排7最大允许充电电流";
CM_ SG_ 2335501985 M2P_PermitMaxDisCharge_I_B7_17 "汇流排7最大允许放电电流";
CM_ SG_ 2335501986 M2P_Measure_Vol_B7_18 "汇流排7所有高压在线电柜外侧电压平均值    ";
CM_ SG_ 2335501986 M2P_Current_B7_18 "汇流排7所有电柜电流累加和";
CM_ SG_ 2335501986 M2P_PermitMaxCharge_I_B7_18 "汇流排7最大允许充电电流";
CM_ SG_ 2335501986 M2P_PermitMaxDisCharge_I_B7_18 "汇流排7最大允许放电电流";
CM_ SG_ 2335501987 M2P_Measure_Vol_B7_19 "汇流排7所有高压在线电柜外侧电压平均值    ";
CM_ SG_ 2335501987 M2P_Current_B7_19 "汇流排7所有电柜电流累加和";
CM_ SG_ 2335501987 M2P_PermitMaxCharge_I_B7_19 "汇流排7最大允许充电电流";
CM_ SG_ 2335501987 M2P_PermitMaxDisCharge_I_B7_19 "汇流排7最大允许放电电流";
CM_ SG_ 2335501988 M2P_Measure_Vol_B7_20 "汇流排7所有高压在线电柜外侧电压平均值    ";
CM_ SG_ 2335501988 M2P_Current_B7_20 "汇流排7所有电柜电流累加和";
CM_ SG_ 2335501988 M2P_PermitMaxCharge_I_B7_20 "汇流排7最大允许充电电流";
CM_ SG_ 2335501988 M2P_PermitMaxDisCharge_I_B7_20 "汇流排7最大允许放电电流";
CM_ SG_ 2335501989 M2P_Measure_Vol_B7_21 "汇流排7所有高压在线电柜外侧电压平均值    ";
CM_ SG_ 2335501989 M2P_Current_B7_21 "汇流排7所有电柜电流累加和";
CM_ SG_ 2335501989 M2P_PermitMaxCharge_I_B7_21 "汇流排7最大允许充电电流";
CM_ SG_ 2335501989 M2P_PermitMaxDisCharge_I_B7_21 "汇流排7最大允许放电电流";
CM_ SG_ 2335501990 M2P_Measure_Vol_B7_22 "汇流排7所有高压在线电柜外侧电压平均值    ";
CM_ SG_ 2335501990 M2P_Current_B7_22 "汇流排7所有电柜电流累加和";
CM_ SG_ 2335501990 M2P_PermitMaxCharge_I_B7_22 "汇流排7最大允许充电电流";
CM_ SG_ 2335501990 M2P_PermitMaxDisCharge_I_B7_22 "汇流排7最大允许放电电流";
CM_ SG_ 2335501991 M2P_Measure_Vol_B7_23 "汇流排7所有高压在线电柜外侧电压平均值    ";
CM_ SG_ 2335501991 M2P_Current_B7_23 "汇流排7所有电柜电流累加和";
CM_ SG_ 2335501991 M2P_PermitMaxCharge_I_B7_23 "汇流排7最大允许充电电流";
CM_ SG_ 2335501991 M2P_PermitMaxDisCharge_I_B7_23 "汇流排7最大允许放电电流";
CM_ SG_ 2335501992 M2P_Measure_Vol_B7_24 "汇流排7所有高压在线电柜外侧电压平均值    ";
CM_ SG_ 2335501992 M2P_Current_B7_24 "汇流排7所有电柜电流累加和";
CM_ SG_ 2335501992 M2P_PermitMaxCharge_I_B7_24 "汇流排7最大允许充电电流";
CM_ SG_ 2335501992 M2P_PermitMaxDisCharge_I_B7_24 "汇流排7最大允许放电电流";
CM_ SG_ 2335501993 M2P_Measure_Vol_B7_25 "汇流排7所有高压在线电柜外侧电压平均值    ";
CM_ SG_ 2335501993 M2P_Current_B7_25 "汇流排7所有电柜电流累加和";
CM_ SG_ 2335501993 M2P_PermitMaxCharge_I_B7_25 "汇流排7最大允许充电电流";
CM_ SG_ 2335501993 M2P_PermitMaxDisCharge_I_B7_25 "汇流排7最大允许放电电流";
CM_ SG_ 2335501994 M2P_Measure_Vol_B7_26 "汇流排7所有高压在线电柜外侧电压平均值    ";
CM_ SG_ 2335501994 M2P_Current_B7_26 "汇流排7所有电柜电流累加和";
CM_ SG_ 2335501994 M2P_PermitMaxCharge_I_B7_26 "汇流排7最大允许充电电流";
CM_ SG_ 2335501994 M2P_PermitMaxDisCharge_I_B7_26 "汇流排7最大允许放电电流";
CM_ SG_ 2335501995 M2P_Measure_Vol_B7_27 "汇流排7所有高压在线电柜外侧电压平均值    ";
CM_ SG_ 2335501995 M2P_Current_B7_27 "汇流排7所有电柜电流累加和";
CM_ SG_ 2335501995 M2P_PermitMaxCharge_I_B7_27 "汇流排7最大允许充电电流";
CM_ SG_ 2335501995 M2P_PermitMaxDisCharge_I_B7_27 "汇流排7最大允许放电电流";
CM_ SG_ 2335501996 M2P_Measure_Vol_B7_28 "汇流排7所有高压在线电柜外侧电压平均值    ";
CM_ SG_ 2335501996 M2P_Current_B7_28 "汇流排7所有电柜电流累加和";
CM_ SG_ 2335501996 M2P_PermitMaxCharge_I_B7_28 "汇流排7最大允许充电电流";
CM_ SG_ 2335501996 M2P_PermitMaxDisCharge_I_B7_28 "汇流排7最大允许放电电流";
CM_ SG_ 2335501997 M2P_Measure_Vol_B7_29 "汇流排7所有高压在线电柜外侧电压平均值    ";
CM_ SG_ 2335501997 M2P_Current_B7_29 "汇流排7所有电柜电流累加和";
CM_ SG_ 2335501997 M2P_PermitMaxCharge_I_B7_29 "汇流排7最大允许充电电流";
CM_ SG_ 2335501997 M2P_PermitMaxDisCharge_I_B7_29 "汇流排7最大允许放电电流";
CM_ SG_ 2335501998 M2P_Measure_Vol_B7_30 "汇流排7所有高压在线电柜外侧电压平均值    ";
CM_ SG_ 2335501998 M2P_Current_B7_30 "汇流排7所有电柜电流累加和";
CM_ SG_ 2335501998 M2P_PermitMaxCharge_I_B7_30 "汇流排7最大允许充电电流";
CM_ SG_ 2335501998 M2P_PermitMaxDisCharge_I_B7_30 "汇流排7最大允许放电电流";
CM_ SG_ 2335501999 M2P_Measure_Vol_B7_31 "汇流排7所有高压在线电柜外侧电压平均值    ";
CM_ SG_ 2335501999 M2P_Current_B7_31 "汇流排7所有电柜电流累加和";
CM_ SG_ 2335501999 M2P_PermitMaxCharge_I_B7_31 "汇流排7最大允许充电电流";
CM_ SG_ 2335501999 M2P_PermitMaxDisCharge_I_B7_31 "汇流排7最大允许放电电流";
CM_ SG_ 2335567505 M2P_PermitMaxVolt_B7_01 "汇流排7最高允许充电电压 （配置量）";
CM_ SG_ 2335567505 M2P_PermitMinVolt_B7_01 "汇流排7最低允许放电电压 （配置量）";
CM_ SG_ 2335567505 M2P_PermitMaxPow_Chg_B7_01 "汇流排7最大允许充电功率";
CM_ SG_ 2335567505 M2P_PermitMaxPow_DisChg_B7_01 "汇流排7最大允许放电功率";
CM_ SG_ 2335567506 M2P_PermitMaxVolt_B7_02 "汇流排7最高允许充电电压 （配置量）";
CM_ SG_ 2335567506 M2P_PermitMinVolt_B7_02 "汇流排7最低允许放电电压 （配置量）";
CM_ SG_ 2335567506 M2P_PermitMaxPow_Chg_B7_02 "汇流排7最大允许充电功率";
CM_ SG_ 2335567506 M2P_PermitMaxPow_DisChg_B7_02 "汇流排7最大允许放电功率";
CM_ SG_ 2335567507 M2P_PermitMaxVolt_B7_03 "汇流排7最高允许充电电压 （配置量）";
CM_ SG_ 2335567507 M2P_PermitMinVolt_B7_03 "汇流排7最低允许放电电压 （配置量）";
CM_ SG_ 2335567507 M2P_PermitMaxPow_Chg_B7_03 "汇流排7最大允许充电功率";
CM_ SG_ 2335567507 M2P_PermitMaxPow_DisChg_B7_03 "汇流排7最大允许放电功率";
CM_ SG_ 2335567508 M2P_PermitMaxVolt_B7_04 "汇流排7最高允许充电电压 （配置量）";
CM_ SG_ 2335567508 M2P_PermitMinVolt_B7_04 "汇流排7最低允许放电电压 （配置量）";
CM_ SG_ 2335567508 M2P_PermitMaxPow_Chg_B7_04 "汇流排7最大允许充电功率";
CM_ SG_ 2335567508 M2P_PermitMaxPow_DisChg_B7_04 "汇流排7最大允许放电功率";
CM_ SG_ 2335567509 M2P_PermitMaxVolt_B7_05 "汇流排7最高允许充电电压 （配置量）";
CM_ SG_ 2335567509 M2P_PermitMinVolt_B7_05 "汇流排7最低允许放电电压 （配置量）";
CM_ SG_ 2335567509 M2P_PermitMaxPow_Chg_B7_05 "汇流排7最大允许充电功率";
CM_ SG_ 2335567509 M2P_PermitMaxPow_DisChg_B7_05 "汇流排7最大允许放电功率";
CM_ SG_ 2335567510 M2P_PermitMaxVolt_B7_06 "汇流排7最高允许充电电压 （配置量）";
CM_ SG_ 2335567510 M2P_PermitMinVolt_B7_06 "汇流排7最低允许放电电压 （配置量）";
CM_ SG_ 2335567510 M2P_PermitMaxPow_Chg_B7_06 "汇流排7最大允许充电功率";
CM_ SG_ 2335567510 M2P_PermitMaxPow_DisChg_B7_06 "汇流排7最大允许放电功率";
CM_ SG_ 2335567511 M2P_PermitMaxVolt_B7_07 "汇流排7最高允许充电电压 （配置量）";
CM_ SG_ 2335567511 M2P_PermitMinVolt_B7_07 "汇流排7最低允许放电电压 （配置量）";
CM_ SG_ 2335567511 M2P_PermitMaxPow_Chg_B7_07 "汇流排7最大允许充电功率";
CM_ SG_ 2335567511 M2P_PermitMaxPow_DisChg_B7_07 "汇流排7最大允许放电功率";
CM_ SG_ 2335567512 M2P_PermitMaxVolt_B7_08 "汇流排7最高允许充电电压 （配置量）";
CM_ SG_ 2335567512 M2P_PermitMinVolt_B7_08 "汇流排7最低允许放电电压 （配置量）";
CM_ SG_ 2335567512 M2P_PermitMaxPow_Chg_B7_08 "汇流排7最大允许充电功率";
CM_ SG_ 2335567512 M2P_PermitMaxPow_DisChg_B7_08 "汇流排7最大允许放电功率";
CM_ SG_ 2335567513 M2P_PermitMaxVolt_B7_09 "汇流排7最高允许充电电压 （配置量）";
CM_ SG_ 2335567513 M2P_PermitMinVolt_B7_09 "汇流排7最低允许放电电压 （配置量）";
CM_ SG_ 2335567513 M2P_PermitMaxPow_Chg_B7_09 "汇流排7最大允许充电功率";
CM_ SG_ 2335567513 M2P_PermitMaxPow_DisChg_B7_09 "汇流排7最大允许放电功率";
CM_ SG_ 2335567514 M2P_PermitMaxVolt_B7_10 "汇流排7最高允许充电电压 （配置量）";
CM_ SG_ 2335567514 M2P_PermitMinVolt_B7_10 "汇流排7最低允许放电电压 （配置量）";
CM_ SG_ 2335567514 M2P_PermitMaxPow_Chg_B7_10 "汇流排7最大允许充电功率";
CM_ SG_ 2335567514 M2P_PermitMaxPow_DisChg_B7_10 "汇流排7最大允许放电功率";
CM_ SG_ 2335567515 M2P_PermitMaxVolt_B7_11 "汇流排7最高允许充电电压 （配置量）";
CM_ SG_ 2335567515 M2P_PermitMinVolt_B7_11 "汇流排7最低允许放电电压 （配置量）";
CM_ SG_ 2335567515 M2P_PermitMaxPow_Chg_B7_11 "汇流排7最大允许充电功率";
CM_ SG_ 2335567515 M2P_PermitMaxPow_DisChg_B7_11 "汇流排7最大允许放电功率";
CM_ SG_ 2335567516 M2P_PermitMaxVolt_B7_12 "汇流排7最高允许充电电压 （配置量）";
CM_ SG_ 2335567516 M2P_PermitMinVolt_B7_12 "汇流排7最低允许放电电压 （配置量）";
CM_ SG_ 2335567516 M2P_PermitMaxPow_Chg_B7_12 "汇流排7最大允许充电功率";
CM_ SG_ 2335567516 M2P_PermitMaxPow_DisChg_B7_12 "汇流排7最大允许放电功率";
CM_ SG_ 2335567517 M2P_PermitMaxVolt_B7_13 "汇流排7最高允许充电电压 （配置量）";
CM_ SG_ 2335567517 M2P_PermitMinVolt_B7_13 "汇流排7最低允许放电电压 （配置量）";
CM_ SG_ 2335567517 M2P_PermitMaxPow_Chg_B7_13 "汇流排7最大允许充电功率";
CM_ SG_ 2335567517 M2P_PermitMaxPow_DisChg_B7_13 "汇流排7最大允许放电功率";
CM_ SG_ 2335567518 M2P_PermitMaxVolt_B7_14 "汇流排7最高允许充电电压 （配置量）";
CM_ SG_ 2335567518 M2P_PermitMinVolt_B7_14 "汇流排7最低允许放电电压 （配置量）";
CM_ SG_ 2335567518 M2P_PermitMaxPow_Chg_B7_14 "汇流排7最大允许充电功率";
CM_ SG_ 2335567518 M2P_PermitMaxPow_DisChg_B7_14 "汇流排7最大允许放电功率";
CM_ SG_ 2335567519 M2P_PermitMaxVolt_B7_15 "汇流排7最高允许充电电压 （配置量）";
CM_ SG_ 2335567519 M2P_PermitMinVolt_B7_15 "汇流排7最低允许放电电压 （配置量）";
CM_ SG_ 2335567519 M2P_PermitMaxPow_Chg_B7_15 "汇流排7最大允许充电功率";
CM_ SG_ 2335567519 M2P_PermitMaxPow_DisChg_B7_15 "汇流排7最大允许放电功率";
CM_ SG_ 2335567520 M2P_PermitMaxVolt_B7_16 "汇流排7最高允许充电电压 （配置量）";
CM_ SG_ 2335567520 M2P_PermitMinVolt_B7_16 "汇流排7最低允许放电电压 （配置量）";
CM_ SG_ 2335567520 M2P_PermitMaxPow_Chg_B7_16 "汇流排7最大允许充电功率";
CM_ SG_ 2335567520 M2P_PermitMaxPow_DisChg_B7_16 "汇流排7最大允许放电功率";
CM_ SG_ 2335567521 M2P_PermitMaxVolt_B7_17 "汇流排7最高允许充电电压 （配置量）";
CM_ SG_ 2335567521 M2P_PermitMinVolt_B7_17 "汇流排7最低允许放电电压 （配置量）";
CM_ SG_ 2335567521 M2P_PermitMaxPow_Chg_B7_17 "汇流排7最大允许充电功率";
CM_ SG_ 2335567521 M2P_PermitMaxPow_DisChg_B7_17 "汇流排7最大允许放电功率";
CM_ SG_ 2335567522 M2P_PermitMaxVolt_B7_18 "汇流排7最高允许充电电压 （配置量）";
CM_ SG_ 2335567522 M2P_PermitMinVolt_B7_18 "汇流排7最低允许放电电压 （配置量）";
CM_ SG_ 2335567522 M2P_PermitMaxPow_Chg_B7_18 "汇流排7最大允许充电功率";
CM_ SG_ 2335567522 M2P_PermitMaxPow_DisChg_B7_18 "汇流排7最大允许放电功率";
CM_ SG_ 2335567523 M2P_PermitMaxVolt_B7_19 "汇流排7最高允许充电电压 （配置量）";
CM_ SG_ 2335567523 M2P_PermitMinVolt_B7_19 "汇流排7最低允许放电电压 （配置量）";
CM_ SG_ 2335567523 M2P_PermitMaxPow_Chg_B7_19 "汇流排7最大允许充电功率";
CM_ SG_ 2335567523 M2P_PermitMaxPow_DisChg_B7_19 "汇流排7最大允许放电功率";
CM_ SG_ 2335567524 M2P_PermitMaxVolt_B7_20 "汇流排7最高允许充电电压 （配置量）";
CM_ SG_ 2335567524 M2P_PermitMinVolt_B7_20 "汇流排7最低允许放电电压 （配置量）";
CM_ SG_ 2335567524 M2P_PermitMaxPow_Chg_B7_20 "汇流排7最大允许充电功率";
CM_ SG_ 2335567524 M2P_PermitMaxPow_DisChg_B7_20 "汇流排7最大允许放电功率";
CM_ SG_ 2335567525 M2P_PermitMaxVolt_B7_21 "汇流排7最高允许充电电压 （配置量）";
CM_ SG_ 2335567525 M2P_PermitMinVolt_B7_21 "汇流排7最低允许放电电压 （配置量）";
CM_ SG_ 2335567525 M2P_PermitMaxPow_Chg_B7_21 "汇流排7最大允许充电功率";
CM_ SG_ 2335567525 M2P_PermitMaxPow_DisChg_B7_21 "汇流排7最大允许放电功率";
CM_ SG_ 2335567526 M2P_PermitMaxVolt_B7_22 "汇流排7最高允许充电电压 （配置量）";
CM_ SG_ 2335567526 M2P_PermitMinVolt_B7_22 "汇流排7最低允许放电电压 （配置量）";
CM_ SG_ 2335567526 M2P_PermitMaxPow_Chg_B7_22 "汇流排7最大允许充电功率";
CM_ SG_ 2335567526 M2P_PermitMaxPow_DisChg_B7_22 "汇流排7最大允许放电功率";
CM_ SG_ 2335567527 M2P_PermitMaxVolt_B7_23 "汇流排7最高允许充电电压 （配置量）";
CM_ SG_ 2335567527 M2P_PermitMinVolt_B7_23 "汇流排7最低允许放电电压 （配置量）";
CM_ SG_ 2335567527 M2P_PermitMaxPow_Chg_B7_23 "汇流排7最大允许充电功率";
CM_ SG_ 2335567527 M2P_PermitMaxPow_DisChg_B7_23 "汇流排7最大允许放电功率";
CM_ SG_ 2335567528 M2P_PermitMaxVolt_B7_24 "汇流排7最高允许充电电压 （配置量）";
CM_ SG_ 2335567528 M2P_PermitMinVolt_B7_24 "汇流排7最低允许放电电压 （配置量）";
CM_ SG_ 2335567528 M2P_PermitMaxPow_Chg_B7_24 "汇流排7最大允许充电功率";
CM_ SG_ 2335567528 M2P_PermitMaxPow_DisChg_B7_24 "汇流排7最大允许放电功率";
CM_ SG_ 2335567529 M2P_PermitMaxVolt_B7_25 "汇流排7最高允许充电电压 （配置量）";
CM_ SG_ 2335567529 M2P_PermitMinVolt_B7_25 "汇流排7最低允许放电电压 （配置量）";
CM_ SG_ 2335567529 M2P_PermitMaxPow_Chg_B7_25 "汇流排7最大允许充电功率";
CM_ SG_ 2335567529 M2P_PermitMaxPow_DisChg_B7_25 "汇流排7最大允许放电功率";
CM_ SG_ 2335567530 M2P_PermitMaxVolt_B7_26 "汇流排7最高允许充电电压 （配置量）";
CM_ SG_ 2335567530 M2P_PermitMinVolt_B7_26 "汇流排7最低允许放电电压 （配置量）";
CM_ SG_ 2335567530 M2P_PermitMaxPow_Chg_B7_26 "汇流排7最大允许充电功率";
CM_ SG_ 2335567530 M2P_PermitMaxPow_DisChg_B7_26 "汇流排7最大允许放电功率";
CM_ SG_ 2335567531 M2P_PermitMaxVolt_B7_27 "汇流排7最高允许充电电压 （配置量）";
CM_ SG_ 2335567531 M2P_PermitMinVolt_B7_27 "汇流排7最低允许放电电压 （配置量）";
CM_ SG_ 2335567531 M2P_PermitMaxPow_Chg_B7_27 "汇流排7最大允许充电功率";
CM_ SG_ 2335567531 M2P_PermitMaxPow_DisChg_B7_27 "汇流排7最大允许放电功率";
CM_ SG_ 2335567532 M2P_PermitMaxVolt_B7_28 "汇流排7最高允许充电电压 （配置量）";
CM_ SG_ 2335567532 M2P_PermitMinVolt_B7_28 "汇流排7最低允许放电电压 （配置量）";
CM_ SG_ 2335567532 M2P_PermitMaxPow_Chg_B7_28 "汇流排7最大允许充电功率";
CM_ SG_ 2335567532 M2P_PermitMaxPow_DisChg_B7_28 "汇流排7最大允许放电功率";
CM_ SG_ 2335567533 M2P_PermitMaxVolt_B7_29 "汇流排7最高允许充电电压 （配置量）";
CM_ SG_ 2335567533 M2P_PermitMinVolt_B7_29 "汇流排7最低允许放电电压 （配置量）";
CM_ SG_ 2335567533 M2P_PermitMaxPow_Chg_B7_29 "汇流排7最大允许充电功率";
CM_ SG_ 2335567533 M2P_PermitMaxPow_DisChg_B7_29 "汇流排7最大允许放电功率";
CM_ SG_ 2335567534 M2P_PermitMaxVolt_B7_30 "汇流排7最高允许充电电压 （配置量）";
CM_ SG_ 2335567534 M2P_PermitMinVolt_B7_30 "汇流排7最低允许放电电压 （配置量）";
CM_ SG_ 2335567534 M2P_PermitMaxPow_Chg_B7_30 "汇流排7最大允许充电功率";
CM_ SG_ 2335567534 M2P_PermitMaxPow_DisChg_B7_30 "汇流排7最大允许放电功率";
CM_ SG_ 2335567535 M2P_PermitMaxVolt_B7_31 "汇流排7最高允许充电电压 （配置量）";
CM_ SG_ 2335567535 M2P_PermitMinVolt_B7_31 "汇流排7最低允许放电电压 （配置量）";
CM_ SG_ 2335567535 M2P_PermitMaxPow_Chg_B7_31 "汇流排7最大允许充电功率";
CM_ SG_ 2335567535 M2P_PermitMaxPow_DisChg_B7_31 "汇流排7最大允许放电功率";
CM_ SG_ 2335633041 M2P_Power_B7_01 "汇流排7实时功率";
CM_ SG_ 2335633041 M2P_SysremEngy_Chg_B7_01 "汇流排7充电剩余能量";
CM_ SG_ 2335633041 M2P_SysremEngy_DisChg_B7_01 "汇流排7放电剩余能量";
CM_ SG_ 2335633041 M2P_SysMaxVolt_B7_01 "汇流排7单体最大电压  ";
CM_ SG_ 2335633042 M2P_Power_B7_02 "汇流排7实时功率";
CM_ SG_ 2335633042 M2P_SysremEngy_Chg_B7_02 "汇流排7充电剩余能量";
CM_ SG_ 2335633042 M2P_SysremEngy_DisChg_B7_02 "汇流排7放电剩余能量";
CM_ SG_ 2335633042 M2P_SysMaxVolt_B7_02 "汇流排7单体最大电压  ";
CM_ SG_ 2335633043 M2P_Power_B7_03 "汇流排7实时功率";
CM_ SG_ 2335633043 M2P_SysremEngy_Chg_B7_03 "汇流排7充电剩余能量";
CM_ SG_ 2335633043 M2P_SysremEngy_DisChg_B7_03 "汇流排7放电剩余能量";
CM_ SG_ 2335633043 M2P_SysMaxVolt_B7_03 "汇流排7单体最大电压  ";
CM_ SG_ 2335633044 M2P_Power_B7_04 "汇流排7实时功率";
CM_ SG_ 2335633044 M2P_SysremEngy_Chg_B7_04 "汇流排7充电剩余能量";
CM_ SG_ 2335633044 M2P_SysremEngy_DisChg_B7_04 "汇流排7放电剩余能量";
CM_ SG_ 2335633044 M2P_SysMaxVolt_B7_04 "汇流排7单体最大电压  ";
CM_ SG_ 2335633045 M2P_Power_B7_05 "汇流排7实时功率";
CM_ SG_ 2335633045 M2P_SysremEngy_Chg_B7_05 "汇流排7充电剩余能量";
CM_ SG_ 2335633045 M2P_SysremEngy_DisChg_B7_05 "汇流排7放电剩余能量";
CM_ SG_ 2335633045 M2P_SysMaxVolt_B7_05 "汇流排7单体最大电压  ";
CM_ SG_ 2335633046 M2P_Power_B7_06 "汇流排7实时功率";
CM_ SG_ 2335633046 M2P_SysremEngy_Chg_B7_06 "汇流排7充电剩余能量";
CM_ SG_ 2335633046 M2P_SysremEngy_DisChg_B7_06 "汇流排7放电剩余能量";
CM_ SG_ 2335633046 M2P_SysMaxVolt_B7_06 "汇流排7单体最大电压  ";
CM_ SG_ 2335633047 M2P_Power_B7_07 "汇流排7实时功率";
CM_ SG_ 2335633047 M2P_SysremEngy_Chg_B7_07 "汇流排7充电剩余能量";
CM_ SG_ 2335633047 M2P_SysremEngy_DisChg_B7_07 "汇流排7放电剩余能量";
CM_ SG_ 2335633047 M2P_SysMaxVolt_B7_07 "汇流排7单体最大电压  ";
CM_ SG_ 2335633048 M2P_Power_B7_08 "汇流排7实时功率";
CM_ SG_ 2335633048 M2P_SysremEngy_Chg_B7_08 "汇流排7充电剩余能量";
CM_ SG_ 2335633048 M2P_SysremEngy_DisChg_B7_08 "汇流排7放电剩余能量";
CM_ SG_ 2335633048 M2P_SysMaxVolt_B7_08 "汇流排7单体最大电压  ";
CM_ SG_ 2335633049 M2P_Power_B7_09 "汇流排7实时功率";
CM_ SG_ 2335633049 M2P_SysremEngy_Chg_B7_09 "汇流排7充电剩余能量";
CM_ SG_ 2335633049 M2P_SysremEngy_DisChg_B7_09 "汇流排7放电剩余能量";
CM_ SG_ 2335633049 M2P_SysMaxVolt_B7_09 "汇流排7单体最大电压  ";
CM_ SG_ 2335633050 M2P_Power_B7_10 "汇流排7实时功率";
CM_ SG_ 2335633050 M2P_SysremEngy_Chg_B7_10 "汇流排7充电剩余能量";
CM_ SG_ 2335633050 M2P_SysremEngy_DisChg_B7_10 "汇流排7放电剩余能量";
CM_ SG_ 2335633050 M2P_SysMaxVolt_B7_10 "汇流排7单体最大电压  ";
CM_ SG_ 2335633051 M2P_Power_B7_11 "汇流排7实时功率";
CM_ SG_ 2335633051 M2P_SysremEngy_Chg_B7_11 "汇流排7充电剩余能量";
CM_ SG_ 2335633051 M2P_SysremEngy_DisChg_B7_11 "汇流排7放电剩余能量";
CM_ SG_ 2335633051 M2P_SysMaxVolt_B7_11 "汇流排7单体最大电压  ";
CM_ SG_ 2335633052 M2P_Power_B7_12 "汇流排7实时功率";
CM_ SG_ 2335633052 M2P_SysremEngy_Chg_B7_12 "汇流排7充电剩余能量";
CM_ SG_ 2335633052 M2P_SysremEngy_DisChg_B7_12 "汇流排7放电剩余能量";
CM_ SG_ 2335633052 M2P_SysMaxVolt_B7_12 "汇流排7单体最大电压  ";
CM_ SG_ 2335633053 M2P_Power_B7_13 "汇流排7实时功率";
CM_ SG_ 2335633053 M2P_SysremEngy_Chg_B7_13 "汇流排7充电剩余能量";
CM_ SG_ 2335633053 M2P_SysremEngy_DisChg_B7_13 "汇流排7放电剩余能量";
CM_ SG_ 2335633053 M2P_SysMaxVolt_B7_13 "汇流排7单体最大电压  ";
CM_ SG_ 2335633054 M2P_Power_B7_14 "汇流排7实时功率";
CM_ SG_ 2335633054 M2P_SysremEngy_Chg_B7_14 "汇流排7充电剩余能量";
CM_ SG_ 2335633054 M2P_SysremEngy_DisChg_B7_14 "汇流排7放电剩余能量";
CM_ SG_ 2335633054 M2P_SysMaxVolt_B7_14 "汇流排7单体最大电压  ";
CM_ SG_ 2335633055 M2P_Power_B7_15 "汇流排7实时功率";
CM_ SG_ 2335633055 M2P_SysremEngy_Chg_B7_15 "汇流排7充电剩余能量";
CM_ SG_ 2335633055 M2P_SysremEngy_DisChg_B7_15 "汇流排7放电剩余能量";
CM_ SG_ 2335633055 M2P_SysMaxVolt_B7_15 "汇流排7单体最大电压  ";
CM_ SG_ 2335633056 M2P_Power_B7_16 "汇流排7实时功率";
CM_ SG_ 2335633056 M2P_SysremEngy_Chg_B7_16 "汇流排7充电剩余能量";
CM_ SG_ 2335633056 M2P_SysremEngy_DisChg_B7_16 "汇流排7放电剩余能量";
CM_ SG_ 2335633056 M2P_SysMaxVolt_B7_16 "汇流排7单体最大电压  ";
CM_ SG_ 2335633057 M2P_Power_B7_17 "汇流排7实时功率";
CM_ SG_ 2335633057 M2P_SysremEngy_Chg_B7_17 "汇流排7充电剩余能量";
CM_ SG_ 2335633057 M2P_SysremEngy_DisChg_B7_17 "汇流排7放电剩余能量";
CM_ SG_ 2335633057 M2P_SysMaxVolt_B7_17 "汇流排7单体最大电压  ";
CM_ SG_ 2335633058 M2P_Power_B7_18 "汇流排7实时功率";
CM_ SG_ 2335633058 M2P_SysremEngy_Chg_B7_18 "汇流排7充电剩余能量";
CM_ SG_ 2335633058 M2P_SysremEngy_DisChg_B7_18 "汇流排7放电剩余能量";
CM_ SG_ 2335633058 M2P_SysMaxVolt_B7_18 "汇流排7单体最大电压  ";
CM_ SG_ 2335633059 M2P_Power_B7_19 "汇流排7实时功率";
CM_ SG_ 2335633059 M2P_SysremEngy_Chg_B7_19 "汇流排7充电剩余能量";
CM_ SG_ 2335633059 M2P_SysremEngy_DisChg_B7_19 "汇流排7放电剩余能量";
CM_ SG_ 2335633059 M2P_SysMaxVolt_B7_19 "汇流排7单体最大电压  ";
CM_ SG_ 2335633060 M2P_Power_B7_20 "汇流排7实时功率";
CM_ SG_ 2335633060 M2P_SysremEngy_Chg_B7_20 "汇流排7充电剩余能量";
CM_ SG_ 2335633060 M2P_SysremEngy_DisChg_B7_20 "汇流排7放电剩余能量";
CM_ SG_ 2335633060 M2P_SysMaxVolt_B7_20 "汇流排7单体最大电压  ";
CM_ SG_ 2335633061 M2P_Power_B7_21 "汇流排7实时功率";
CM_ SG_ 2335633061 M2P_SysremEngy_Chg_B7_21 "汇流排7充电剩余能量";
CM_ SG_ 2335633061 M2P_SysremEngy_DisChg_B7_21 "汇流排7放电剩余能量";
CM_ SG_ 2335633061 M2P_SysMaxVolt_B7_21 "汇流排7单体最大电压  ";
CM_ SG_ 2335633062 M2P_Power_B7_22 "汇流排7实时功率";
CM_ SG_ 2335633062 M2P_SysremEngy_Chg_B7_22 "汇流排7充电剩余能量";
CM_ SG_ 2335633062 M2P_SysremEngy_DisChg_B7_22 "汇流排7放电剩余能量";
CM_ SG_ 2335633062 M2P_SysMaxVolt_B7_22 "汇流排7单体最大电压  ";
CM_ SG_ 2335633063 M2P_Power_B7_23 "汇流排7实时功率";
CM_ SG_ 2335633063 M2P_SysremEngy_Chg_B7_23 "汇流排7充电剩余能量";
CM_ SG_ 2335633063 M2P_SysremEngy_DisChg_B7_23 "汇流排7放电剩余能量";
CM_ SG_ 2335633063 M2P_SysMaxVolt_B7_23 "汇流排7单体最大电压  ";
CM_ SG_ 2335633064 M2P_Power_B7_24 "汇流排7实时功率";
CM_ SG_ 2335633064 M2P_SysremEngy_Chg_B7_24 "汇流排7充电剩余能量";
CM_ SG_ 2335633064 M2P_SysremEngy_DisChg_B7_24 "汇流排7放电剩余能量";
CM_ SG_ 2335633064 M2P_SysMaxVolt_B7_24 "汇流排7单体最大电压  ";
CM_ SG_ 2335633065 M2P_Power_B7_25 "汇流排7实时功率";
CM_ SG_ 2335633065 M2P_SysremEngy_Chg_B7_25 "汇流排7充电剩余能量";
CM_ SG_ 2335633065 M2P_SysremEngy_DisChg_B7_25 "汇流排7放电剩余能量";
CM_ SG_ 2335633065 M2P_SysMaxVolt_B7_25 "汇流排7单体最大电压  ";
CM_ SG_ 2335633066 M2P_Power_B7_26 "汇流排7实时功率";
CM_ SG_ 2335633066 M2P_SysremEngy_Chg_B7_26 "汇流排7充电剩余能量";
CM_ SG_ 2335633066 M2P_SysremEngy_DisChg_B7_26 "汇流排7放电剩余能量";
CM_ SG_ 2335633066 M2P_SysMaxVolt_B7_26 "汇流排7单体最大电压  ";
CM_ SG_ 2335633067 M2P_Power_B7_27 "汇流排7实时功率";
CM_ SG_ 2335633067 M2P_SysremEngy_Chg_B7_27 "汇流排7充电剩余能量";
CM_ SG_ 2335633067 M2P_SysremEngy_DisChg_B7_27 "汇流排7放电剩余能量";
CM_ SG_ 2335633067 M2P_SysMaxVolt_B7_27 "汇流排7单体最大电压  ";
CM_ SG_ 2335633068 M2P_Power_B7_28 "汇流排7实时功率";
CM_ SG_ 2335633068 M2P_SysremEngy_Chg_B7_28 "汇流排7充电剩余能量";
CM_ SG_ 2335633068 M2P_SysremEngy_DisChg_B7_28 "汇流排7放电剩余能量";
CM_ SG_ 2335633068 M2P_SysMaxVolt_B7_28 "汇流排7单体最大电压  ";
CM_ SG_ 2335633069 M2P_Power_B7_29 "汇流排7实时功率";
CM_ SG_ 2335633069 M2P_SysremEngy_Chg_B7_29 "汇流排7充电剩余能量";
CM_ SG_ 2335633069 M2P_SysremEngy_DisChg_B7_29 "汇流排7放电剩余能量";
CM_ SG_ 2335633069 M2P_SysMaxVolt_B7_29 "汇流排7单体最大电压  ";
CM_ SG_ 2335633070 M2P_Power_B7_30 "汇流排7实时功率";
CM_ SG_ 2335633070 M2P_SysremEngy_Chg_B7_30 "汇流排7充电剩余能量";
CM_ SG_ 2335633070 M2P_SysremEngy_DisChg_B7_30 "汇流排7放电剩余能量";
CM_ SG_ 2335633070 M2P_SysMaxVolt_B7_30 "汇流排7单体最大电压  ";
CM_ SG_ 2335633071 M2P_Power_B7_31 "汇流排7实时功率";
CM_ SG_ 2335633071 M2P_SysremEngy_Chg_B7_31 "汇流排7充电剩余能量";
CM_ SG_ 2335633071 M2P_SysremEngy_DisChg_B7_31 "汇流排7放电剩余能量";
CM_ SG_ 2335633071 M2P_SysMaxVolt_B7_31 "汇流排7单体最大电压  ";
CM_ SG_ 2335698577 M2P_SysMinVolt_B7_01 "汇流排7单体最小电压";
CM_ SG_ 2335698577 M2P_SysAvgVolt_B7_01 "汇流排7单体平均电压";
CM_ SG_ 2335698577 M2P_BMS_Status_B7 "汇流排7能量状态";
CM_ SG_ 2335698577 M2P_SOC_B7 "汇流排7系统SOC";
CM_ SG_ 2335698577 M2P_SOH_B7 "汇流排7系统SOH";
CM_ SG_ 2335698577 Reserved_01 "预留";
CM_ SG_ 2335698578 M2P_SysMinVolt_B7_02 "汇流排7单体最小电压";
CM_ SG_ 2335698578 M2P_SysAvgVolt_B7_02 "汇流排7单体平均电压";
CM_ SG_ 2335698578 M2P_BMS_Status_B7 "汇流排7能量状态";
CM_ SG_ 2335698578 M2P_SOC_B7 "汇流排7系统SOC";
CM_ SG_ 2335698578 M2P_SOH_B7 "汇流排7系统SOH";
CM_ SG_ 2335698578 Reserved_02 "预留";
CM_ SG_ 2335698579 M2P_SysMinVolt_B7_03 "汇流排7单体最小电压";
CM_ SG_ 2335698579 M2P_SysAvgVolt_B7_03 "汇流排7单体平均电压";
CM_ SG_ 2335698579 M2P_BMS_Status_B7 "汇流排7能量状态";
CM_ SG_ 2335698579 M2P_SOC_B7 "汇流排7系统SOC";
CM_ SG_ 2335698579 M2P_SOH_B7 "汇流排7系统SOH";
CM_ SG_ 2335698579 Reserved_03 "预留";
CM_ SG_ 2335698580 M2P_SysMinVolt_B7_04 "汇流排7单体最小电压";
CM_ SG_ 2335698580 M2P_SysAvgVolt_B7_04 "汇流排7单体平均电压";
CM_ SG_ 2335698580 M2P_BMS_Status_B7 "汇流排7能量状态";
CM_ SG_ 2335698580 M2P_SOC_B7 "汇流排7系统SOC";
CM_ SG_ 2335698580 M2P_SOH_B7 "汇流排7系统SOH";
CM_ SG_ 2335698580 Reserved_04 "预留";
CM_ SG_ 2335698581 M2P_SysMinVolt_B7_05 "汇流排7单体最小电压";
CM_ SG_ 2335698581 M2P_SysAvgVolt_B7_05 "汇流排7单体平均电压";
CM_ SG_ 2335698581 M2P_BMS_Status_B7 "汇流排7能量状态";
CM_ SG_ 2335698581 M2P_SOC_B7 "汇流排7系统SOC";
CM_ SG_ 2335698581 M2P_SOH_B7 "汇流排7系统SOH";
CM_ SG_ 2335698581 Reserved_05 "预留";
CM_ SG_ 2335698582 M2P_SysMinVolt_B7_06 "汇流排7单体最小电压";
CM_ SG_ 2335698582 M2P_SysAvgVolt_B7_06 "汇流排7单体平均电压";
CM_ SG_ 2335698582 M2P_BMS_Status_B7 "汇流排7能量状态";
CM_ SG_ 2335698582 M2P_SOC_B7 "汇流排7系统SOC";
CM_ SG_ 2335698582 M2P_SOH_B7 "汇流排7系统SOH";
CM_ SG_ 2335698582 Reserved_06 "预留";
CM_ SG_ 2335698583 M2P_SysMinVolt_B7_07 "汇流排7单体最小电压";
CM_ SG_ 2335698583 M2P_SysAvgVolt_B7_07 "汇流排7单体平均电压";
CM_ SG_ 2335698583 M2P_BMS_Status_B7 "汇流排7能量状态";
CM_ SG_ 2335698583 M2P_SOC_B7 "汇流排7系统SOC";
CM_ SG_ 2335698583 M2P_SOH_B7 "汇流排7系统SOH";
CM_ SG_ 2335698583 Reserved_07 "预留";
CM_ SG_ 2335698584 M2P_SysMinVolt_B7_08 "汇流排7单体最小电压";
CM_ SG_ 2335698584 M2P_SysAvgVolt_B7_08 "汇流排7单体平均电压";
CM_ SG_ 2335698584 M2P_BMS_Status_B7 "汇流排7能量状态";
CM_ SG_ 2335698584 M2P_SOC_B7 "汇流排7系统SOC";
CM_ SG_ 2335698584 M2P_SOH_B7 "汇流排7系统SOH";
CM_ SG_ 2335698584 Reserved_08 "预留";
CM_ SG_ 2335698585 M2P_SysMinVolt_B7_09 "汇流排7单体最小电压";
CM_ SG_ 2335698585 M2P_SysAvgVolt_B7_09 "汇流排7单体平均电压";
CM_ SG_ 2335698585 M2P_BMS_Status_B7 "汇流排7能量状态";
CM_ SG_ 2335698585 M2P_SOC_B7 "汇流排7系统SOC";
CM_ SG_ 2335698585 M2P_SOH_B7 "汇流排7系统SOH";
CM_ SG_ 2335698585 Reserved_09 "预留";
CM_ SG_ 2335698586 M2P_SysMinVolt_B7_10 "汇流排7单体最小电压";
CM_ SG_ 2335698586 M2P_SysAvgVolt_B7_10 "汇流排7单体平均电压";
CM_ SG_ 2335698586 M2P_BMS_Status_B7 "汇流排7能量状态";
CM_ SG_ 2335698586 M2P_SOC_B7 "汇流排7系统SOC";
CM_ SG_ 2335698586 M2P_SOH_B7 "汇流排7系统SOH";
CM_ SG_ 2335698586 Reserved_10 "预留";
CM_ SG_ 2335698587 M2P_SysMinVolt_B7_11 "汇流排7单体最小电压";
CM_ SG_ 2335698587 M2P_SysAvgVolt_B7_11 "汇流排7单体平均电压";
CM_ SG_ 2335698587 M2P_BMS_Status_B7 "汇流排7能量状态";
CM_ SG_ 2335698587 M2P_SOC_B7 "汇流排7系统SOC";
CM_ SG_ 2335698587 M2P_SOH_B7 "汇流排7系统SOH";
CM_ SG_ 2335698587 Reserved_11 "预留";
CM_ SG_ 2335698588 M2P_SysMinVolt_B7_12 "汇流排7单体最小电压";
CM_ SG_ 2335698588 M2P_SysAvgVolt_B7_12 "汇流排7单体平均电压";
CM_ SG_ 2335698588 M2P_BMS_Status_B7 "汇流排7能量状态";
CM_ SG_ 2335698588 M2P_SOC_B7 "汇流排7系统SOC";
CM_ SG_ 2335698588 M2P_SOH_B7 "汇流排7系统SOH";
CM_ SG_ 2335698588 Reserved_12 "预留";
CM_ SG_ 2335698589 M2P_SysMinVolt_B7_13 "汇流排7单体最小电压";
CM_ SG_ 2335698589 M2P_SysAvgVolt_B7_13 "汇流排7单体平均电压";
CM_ SG_ 2335698589 M2P_BMS_Status_B7 "汇流排7能量状态";
CM_ SG_ 2335698589 M2P_SOC_B7 "汇流排7系统SOC";
CM_ SG_ 2335698589 M2P_SOH_B7 "汇流排7系统SOH";
CM_ SG_ 2335698589 Reserved_13 "预留";
CM_ SG_ 2335698590 M2P_SysMinVolt_B7_14 "汇流排7单体最小电压";
CM_ SG_ 2335698590 M2P_SysAvgVolt_B7_14 "汇流排7单体平均电压";
CM_ SG_ 2335698590 M2P_BMS_Status_B7 "汇流排7能量状态";
CM_ SG_ 2335698590 M2P_SOC_B7 "汇流排7系统SOC";
CM_ SG_ 2335698590 M2P_SOH_B7 "汇流排7系统SOH";
CM_ SG_ 2335698590 Reserved_14 "预留";
CM_ SG_ 2335698591 M2P_SysMinVolt_B7_15 "汇流排7单体最小电压";
CM_ SG_ 2335698591 M2P_SysAvgVolt_B7_15 "汇流排7单体平均电压";
CM_ SG_ 2335698591 M2P_BMS_Status_B7 "汇流排7能量状态";
CM_ SG_ 2335698591 M2P_SOC_B7 "汇流排7系统SOC";
CM_ SG_ 2335698591 M2P_SOH_B7 "汇流排7系统SOH";
CM_ SG_ 2335698591 Reserved_15 "预留";
CM_ SG_ 2335698592 M2P_SysMinVolt_B7_16 "汇流排7单体最小电压";
CM_ SG_ 2335698592 M2P_SysAvgVolt_B7_16 "汇流排7单体平均电压";
CM_ SG_ 2335698592 M2P_BMS_Status_B7 "汇流排7能量状态";
CM_ SG_ 2335698592 M2P_SOC_B7 "汇流排7系统SOC";
CM_ SG_ 2335698592 M2P_SOH_B7 "汇流排7系统SOH";
CM_ SG_ 2335698592 Reserved_16 "预留";
CM_ SG_ 2335698593 M2P_SysMinVolt_B7_17 "汇流排7单体最小电压";
CM_ SG_ 2335698593 M2P_SysAvgVolt_B7_17 "汇流排7单体平均电压";
CM_ SG_ 2335698593 M2P_BMS_Status_B7 "汇流排7能量状态";
CM_ SG_ 2335698593 M2P_SOC_B7 "汇流排7系统SOC";
CM_ SG_ 2335698593 M2P_SOH_B7 "汇流排7系统SOH";
CM_ SG_ 2335698593 Reserved_17 "预留";
CM_ SG_ 2335698594 M2P_SysMinVolt_B7_18 "汇流排7单体最小电压";
CM_ SG_ 2335698594 M2P_SysAvgVolt_B7_18 "汇流排7单体平均电压";
CM_ SG_ 2335698594 M2P_BMS_Status_B7 "汇流排7能量状态";
CM_ SG_ 2335698594 M2P_SOC_B7 "汇流排7系统SOC";
CM_ SG_ 2335698594 M2P_SOH_B7 "汇流排7系统SOH";
CM_ SG_ 2335698594 Reserved_18 "预留";
CM_ SG_ 2335698595 M2P_SysMinVolt_B7_19 "汇流排7单体最小电压";
CM_ SG_ 2335698595 M2P_SysAvgVolt_B7_19 "汇流排7单体平均电压";
CM_ SG_ 2335698595 M2P_BMS_Status_B7 "汇流排7能量状态";
CM_ SG_ 2335698595 M2P_SOC_B7 "汇流排7系统SOC";
CM_ SG_ 2335698595 M2P_SOH_B7 "汇流排7系统SOH";
CM_ SG_ 2335698595 Reserved_19 "预留";
CM_ SG_ 2335698596 M2P_SysMinVolt_B7_20 "汇流排7单体最小电压";
CM_ SG_ 2335698596 M2P_SysAvgVolt_B7_20 "汇流排7单体平均电压";
CM_ SG_ 2335698596 M2P_BMS_Status_B7 "汇流排7能量状态";
CM_ SG_ 2335698596 M2P_SOC_B7 "汇流排7系统SOC";
CM_ SG_ 2335698596 M2P_SOH_B7 "汇流排7系统SOH";
CM_ SG_ 2335698596 Reserved_20 "预留";
CM_ SG_ 2335698597 M2P_SysMinVolt_B7_21 "汇流排7单体最小电压";
CM_ SG_ 2335698597 M2P_SysAvgVolt_B7_21 "汇流排7单体平均电压";
CM_ SG_ 2335698597 M2P_BMS_Status_B7 "汇流排7能量状态";
CM_ SG_ 2335698597 M2P_SOC_B7 "汇流排7系统SOC";
CM_ SG_ 2335698597 M2P_SOH_B7 "汇流排7系统SOH";
CM_ SG_ 2335698597 Reserved_21 "预留";
CM_ SG_ 2335698598 M2P_SysMinVolt_B7_22 "汇流排7单体最小电压";
CM_ SG_ 2335698598 M2P_SysAvgVolt_B7_22 "汇流排7单体平均电压";
CM_ SG_ 2335698598 M2P_BMS_Status_B7 "汇流排7能量状态";
CM_ SG_ 2335698598 M2P_SOC_B7 "汇流排7系统SOC";
CM_ SG_ 2335698598 M2P_SOH_B7 "汇流排7系统SOH";
CM_ SG_ 2335698598 Reserved_22 "预留";
CM_ SG_ 2335698599 M2P_SysMinVolt_B7_23 "汇流排7单体最小电压";
CM_ SG_ 2335698599 M2P_SysAvgVolt_B7_23 "汇流排7单体平均电压";
CM_ SG_ 2335698599 M2P_BMS_Status_B7 "汇流排7能量状态";
CM_ SG_ 2335698599 M2P_SOC_B7 "汇流排7系统SOC";
CM_ SG_ 2335698599 M2P_SOH_B7 "汇流排7系统SOH";
CM_ SG_ 2335698599 Reserved_23 "预留";
CM_ SG_ 2335698600 M2P_SysMinVolt_B7_24 "汇流排7单体最小电压";
CM_ SG_ 2335698600 M2P_SysAvgVolt_B7_24 "汇流排7单体平均电压";
CM_ SG_ 2335698600 M2P_BMS_Status_B7 "汇流排7能量状态";
CM_ SG_ 2335698600 M2P_SOC_B7 "汇流排7系统SOC";
CM_ SG_ 2335698600 M2P_SOH_B7 "汇流排7系统SOH";
CM_ SG_ 2335698600 Reserved_24 "预留";
CM_ SG_ 2335698601 M2P_SysMinVolt_B7_25 "汇流排7单体最小电压";
CM_ SG_ 2335698601 M2P_SysAvgVolt_B7_25 "汇流排7单体平均电压";
CM_ SG_ 2335698601 M2P_BMS_Status_B7 "汇流排7能量状态";
CM_ SG_ 2335698601 M2P_SOC_B7 "汇流排7系统SOC";
CM_ SG_ 2335698601 M2P_SOH_B7 "汇流排7系统SOH";
CM_ SG_ 2335698601 Reserved_25 "预留";
CM_ SG_ 2335698602 M2P_SysMinVolt_B7_26 "汇流排7单体最小电压";
CM_ SG_ 2335698602 M2P_SysAvgVolt_B7_26 "汇流排7单体平均电压";
CM_ SG_ 2335698602 M2P_BMS_Status_B7 "汇流排7能量状态";
CM_ SG_ 2335698602 M2P_SOC_B7 "汇流排7系统SOC";
CM_ SG_ 2335698602 M2P_SOH_B7 "汇流排7系统SOH";
CM_ SG_ 2335698602 Reserved_26 "预留";
CM_ SG_ 2335698603 M2P_SysMinVolt_B7_27 "汇流排7单体最小电压";
CM_ SG_ 2335698603 M2P_SysAvgVolt_B7_27 "汇流排7单体平均电压";
CM_ SG_ 2335698603 M2P_BMS_Status_B7 "汇流排7能量状态";
CM_ SG_ 2335698603 M2P_SOC_B7 "汇流排7系统SOC";
CM_ SG_ 2335698603 M2P_SOH_B7 "汇流排7系统SOH";
CM_ SG_ 2335698603 Reserved_27 "预留";
CM_ SG_ 2335698604 M2P_SysMinVolt_B7_28 "汇流排7单体最小电压";
CM_ SG_ 2335698604 M2P_SysAvgVolt_B7_28 "汇流排7单体平均电压";
CM_ SG_ 2335698604 M2P_BMS_Status_B7 "汇流排7能量状态";
CM_ SG_ 2335698604 M2P_SOC_B7 "汇流排7系统SOC";
CM_ SG_ 2335698604 M2P_SOH_B7 "汇流排7系统SOH";
CM_ SG_ 2335698604 Reserved_28 "预留";
CM_ SG_ 2335698605 M2P_SysMinVolt_B7_29 "汇流排7单体最小电压";
CM_ SG_ 2335698605 M2P_SysAvgVolt_B7_29 "汇流排7单体平均电压";
CM_ SG_ 2335698605 M2P_BMS_Status_B7 "汇流排7能量状态";
CM_ SG_ 2335698605 M2P_SOC_B7 "汇流排7系统SOC";
CM_ SG_ 2335698605 M2P_SOH_B7 "汇流排7系统SOH";
CM_ SG_ 2335698605 Reserved_29 "预留";
CM_ SG_ 2335698606 M2P_SysMinVolt_B7_30 "汇流排7单体最小电压";
CM_ SG_ 2335698606 M2P_SysAvgVolt_B7_30 "汇流排7单体平均电压";
CM_ SG_ 2335698606 M2P_BMS_Status_B7 "汇流排7能量状态";
CM_ SG_ 2335698606 M2P_SOC_B7 "汇流排7系统SOC";
CM_ SG_ 2335698606 M2P_SOH_B7 "汇流排7系统SOH";
CM_ SG_ 2335698606 Reserved_30 "预留";
CM_ SG_ 2335698607 M2P_SysMinVolt_B7_31 "汇流排7单体最小电压";
CM_ SG_ 2335698607 M2P_SysAvgVolt_B7_31 "汇流排7单体平均电压";
CM_ SG_ 2335698607 M2P_BMS_Status_B7 "汇流排7能量状态";
CM_ SG_ 2335698607 M2P_SOC_B7 "汇流排7系统SOC";
CM_ SG_ 2335698607 M2P_SOH_B7 "汇流排7系统SOH";
CM_ SG_ 2335698607 Reserved_31 "预留";
CM_ SG_ 2335764113 M2P_SOE_Charge_B7 "汇流排7系可充电SOE";
CM_ SG_ 2335764113 M2P_SOE_Discharge_B7 "汇流排7系可放电SOE";
CM_ SG_ 2335764113 Reserved_01 "预留";
CM_ SG_ 2335764114 M2P_SOE_Charge_B7 "汇流排7系可充电SOE";
CM_ SG_ 2335764114 M2P_SOE_Discharge_B7 "汇流排7系可放电SOE";
CM_ SG_ 2335764114 Reserved_02 "预留";
CM_ SG_ 2335764115 M2P_SOE_Charge_B7 "汇流排7系可充电SOE";
CM_ SG_ 2335764115 M2P_SOE_Discharge_B7 "汇流排7系可放电SOE";
CM_ SG_ 2335764115 Reserved_03 "预留";
CM_ SG_ 2335764116 M2P_SOE_Charge_B7 "汇流排7系可充电SOE";
CM_ SG_ 2335764116 M2P_SOE_Discharge_B7 "汇流排7系可放电SOE";
CM_ SG_ 2335764116 Reserved_04 "预留";
CM_ SG_ 2335764117 M2P_SOE_Charge_B7 "汇流排7系可充电SOE";
CM_ SG_ 2335764117 M2P_SOE_Discharge_B7 "汇流排7系可放电SOE";
CM_ SG_ 2335764117 Reserved_05 "预留";
CM_ SG_ 2335764118 M2P_SOE_Charge_B7 "汇流排7系可充电SOE";
CM_ SG_ 2335764118 M2P_SOE_Discharge_B7 "汇流排7系可放电SOE";
CM_ SG_ 2335764118 Reserved_06 "预留";
CM_ SG_ 2335764119 M2P_SOE_Charge_B7 "汇流排7系可充电SOE";
CM_ SG_ 2335764119 M2P_SOE_Discharge_B7 "汇流排7系可放电SOE";
CM_ SG_ 2335764119 Reserved_07 "预留";
CM_ SG_ 2335764120 M2P_SOE_Charge_B7 "汇流排7系可充电SOE";
CM_ SG_ 2335764120 M2P_SOE_Discharge_B7 "汇流排7系可放电SOE";
CM_ SG_ 2335764120 Reserved_08 "预留";
CM_ SG_ 2335764121 M2P_SOE_Charge_B7 "汇流排7系可充电SOE";
CM_ SG_ 2335764121 M2P_SOE_Discharge_B7 "汇流排7系可放电SOE";
CM_ SG_ 2335764121 Reserved_09 "预留";
CM_ SG_ 2335764122 M2P_SOE_Charge_B7 "汇流排7系可充电SOE";
CM_ SG_ 2335764122 M2P_SOE_Discharge_B7 "汇流排7系可放电SOE";
CM_ SG_ 2335764122 Reserved_10 "预留";
CM_ SG_ 2335764123 M2P_SOE_Charge_B7 "汇流排7系可充电SOE";
CM_ SG_ 2335764123 M2P_SOE_Discharge_B7 "汇流排7系可放电SOE";
CM_ SG_ 2335764123 Reserved_11 "预留";
CM_ SG_ 2335764124 M2P_SOE_Charge_B7 "汇流排7系可充电SOE";
CM_ SG_ 2335764124 M2P_SOE_Discharge_B7 "汇流排7系可放电SOE";
CM_ SG_ 2335764124 Reserved_12 "预留";
CM_ SG_ 2335764125 M2P_SOE_Charge_B7 "汇流排7系可充电SOE";
CM_ SG_ 2335764125 M2P_SOE_Discharge_B7 "汇流排7系可放电SOE";
CM_ SG_ 2335764125 Reserved_13 "预留";
CM_ SG_ 2335764126 M2P_SOE_Charge_B7 "汇流排7系可充电SOE";
CM_ SG_ 2335764126 M2P_SOE_Discharge_B7 "汇流排7系可放电SOE";
CM_ SG_ 2335764126 Reserved_14 "预留";
CM_ SG_ 2335764127 M2P_SOE_Charge_B7 "汇流排7系可充电SOE";
CM_ SG_ 2335764127 M2P_SOE_Discharge_B7 "汇流排7系可放电SOE";
CM_ SG_ 2335764127 Reserved_15 "预留";
CM_ SG_ 2335764128 M2P_SOE_Charge_B7 "汇流排7系可充电SOE";
CM_ SG_ 2335764128 M2P_SOE_Discharge_B7 "汇流排7系可放电SOE";
CM_ SG_ 2335764128 Reserved_16 "预留";
CM_ SG_ 2335764129 M2P_SOE_Charge_B7 "汇流排7系可充电SOE";
CM_ SG_ 2335764129 M2P_SOE_Discharge_B7 "汇流排7系可放电SOE";
CM_ SG_ 2335764129 Reserved_17 "预留";
CM_ SG_ 2335764130 M2P_SOE_Charge_B7 "汇流排7系可充电SOE";
CM_ SG_ 2335764130 M2P_SOE_Discharge_B7 "汇流排7系可放电SOE";
CM_ SG_ 2335764130 Reserved_18 "预留";
CM_ SG_ 2335764131 M2P_SOE_Charge_B7 "汇流排7系可充电SOE";
CM_ SG_ 2335764131 M2P_SOE_Discharge_B7 "汇流排7系可放电SOE";
CM_ SG_ 2335764131 Reserved_19 "预留";
CM_ SG_ 2335764132 M2P_SOE_Charge_B7 "汇流排7系可充电SOE";
CM_ SG_ 2335764132 M2P_SOE_Discharge_B7 "汇流排7系可放电SOE";
CM_ SG_ 2335764132 Reserved_20 "预留";
CM_ SG_ 2335764133 M2P_SOE_Charge_B7 "汇流排7系可充电SOE";
CM_ SG_ 2335764133 M2P_SOE_Discharge_B7 "汇流排7系可放电SOE";
CM_ SG_ 2335764133 Reserved_21 "预留";
CM_ SG_ 2335764134 M2P_SOE_Charge_B7 "汇流排7系可充电SOE";
CM_ SG_ 2335764134 M2P_SOE_Discharge_B7 "汇流排7系可放电SOE";
CM_ SG_ 2335764134 Reserved_22 "预留";
CM_ SG_ 2335764135 M2P_SOE_Charge_B7 "汇流排7系可充电SOE";
CM_ SG_ 2335764135 M2P_SOE_Discharge_B7 "汇流排7系可放电SOE";
CM_ SG_ 2335764135 Reserved_23 "预留";
CM_ SG_ 2335764136 M2P_SOE_Charge_B7 "汇流排7系可充电SOE";
CM_ SG_ 2335764136 M2P_SOE_Discharge_B7 "汇流排7系可放电SOE";
CM_ SG_ 2335764136 Reserved_24 "预留";
CM_ SG_ 2335764137 M2P_SOE_Charge_B7 "汇流排7系可充电SOE";
CM_ SG_ 2335764137 M2P_SOE_Discharge_B7 "汇流排7系可放电SOE";
CM_ SG_ 2335764137 Reserved_25 "预留";
CM_ SG_ 2335764138 M2P_SOE_Charge_B7 "汇流排7系可充电SOE";
CM_ SG_ 2335764138 M2P_SOE_Discharge_B7 "汇流排7系可放电SOE";
CM_ SG_ 2335764138 Reserved_26 "预留";
CM_ SG_ 2335764139 M2P_SOE_Charge_B7 "汇流排7系可充电SOE";
CM_ SG_ 2335764139 M2P_SOE_Discharge_B7 "汇流排7系可放电SOE";
CM_ SG_ 2335764139 Reserved_27 "预留";
CM_ SG_ 2335764140 M2P_SOE_Charge_B7 "汇流排7系可充电SOE";
CM_ SG_ 2335764140 M2P_SOE_Discharge_B7 "汇流排7系可放电SOE";
CM_ SG_ 2335764140 Reserved_28 "预留";
CM_ SG_ 2335764141 M2P_SOE_Charge_B7 "汇流排7系可充电SOE";
CM_ SG_ 2335764141 M2P_SOE_Discharge_B7 "汇流排7系可放电SOE";
CM_ SG_ 2335764141 Reserved_29 "预留";
CM_ SG_ 2335764142 M2P_SOE_Charge_B7 "汇流排7系可充电SOE";
CM_ SG_ 2335764142 M2P_SOE_Discharge_B7 "汇流排7系可放电SOE";
CM_ SG_ 2335764142 Reserved_30 "预留";
CM_ SG_ 2335764143 M2P_SOE_Charge_B7 "汇流排7系可充电SOE";
CM_ SG_ 2335764143 M2P_SOE_Discharge_B7 "汇流排7系可放电SOE";
CM_ SG_ 2335764143 Reserved_31 "预留";
CM_ SG_ 2335829649 M2P_Measure_Vol_B8_01 "汇流排8所有高压在线电柜外侧电压平均值    ";
CM_ SG_ 2335829649 M2P_Current_B8_01 "汇流排8所有电柜电流累加和";
CM_ SG_ 2335829649 M2P_PermitMaxCharge_I_B8_01 "汇流排8最大允许充电电流";
CM_ SG_ 2335829649 M2P_PermitMaxDisCharge_I_B8_01 "汇流排8最大允许放电电流";
CM_ SG_ 2335829650 M2P_Measure_Vol_B8_02 "汇流排8所有高压在线电柜外侧电压平均值    ";
CM_ SG_ 2335829650 M2P_Current_B8_02 "汇流排8所有电柜电流累加和";
CM_ SG_ 2335829650 M2P_PermitMaxCharge_I_B8_02 "汇流排8最大允许充电电流";
CM_ SG_ 2335829650 M2P_PermitMaxDisCharge_I_B8_02 "汇流排8最大允许放电电流";
CM_ SG_ 2335829651 M2P_Measure_Vol_B8_03 "汇流排8所有高压在线电柜外侧电压平均值    ";
CM_ SG_ 2335829651 M2P_Current_B8_03 "汇流排8所有电柜电流累加和";
CM_ SG_ 2335829651 M2P_PermitMaxCharge_I_B8_03 "汇流排8最大允许充电电流";
CM_ SG_ 2335829651 M2P_PermitMaxDisCharge_I_B8_03 "汇流排8最大允许放电电流";
CM_ SG_ 2335829652 M2P_Measure_Vol_B8_04 "汇流排8所有高压在线电柜外侧电压平均值    ";
CM_ SG_ 2335829652 M2P_Current_B8_04 "汇流排8所有电柜电流累加和";
CM_ SG_ 2335829652 M2P_PermitMaxCharge_I_B8_04 "汇流排8最大允许充电电流";
CM_ SG_ 2335829652 M2P_PermitMaxDisCharge_I_B8_04 "汇流排8最大允许放电电流";
CM_ SG_ 2335829653 M2P_Measure_Vol_B8_05 "汇流排8所有高压在线电柜外侧电压平均值    ";
CM_ SG_ 2335829653 M2P_Current_B8_05 "汇流排8所有电柜电流累加和";
CM_ SG_ 2335829653 M2P_PermitMaxCharge_I_B8_05 "汇流排8最大允许充电电流";
CM_ SG_ 2335829653 M2P_PermitMaxDisCharge_I_B8_05 "汇流排8最大允许放电电流";
CM_ SG_ 2335829654 M2P_Measure_Vol_B8_06 "汇流排8所有高压在线电柜外侧电压平均值    ";
CM_ SG_ 2335829654 M2P_Current_B8_06 "汇流排8所有电柜电流累加和";
CM_ SG_ 2335829654 M2P_PermitMaxCharge_I_B8_06 "汇流排8最大允许充电电流";
CM_ SG_ 2335829654 M2P_PermitMaxDisCharge_I_B8_06 "汇流排8最大允许放电电流";
CM_ SG_ 2335829655 M2P_Measure_Vol_B8_07 "汇流排8所有高压在线电柜外侧电压平均值    ";
CM_ SG_ 2335829655 M2P_Current_B8_07 "汇流排8所有电柜电流累加和";
CM_ SG_ 2335829655 M2P_PermitMaxCharge_I_B8_07 "汇流排8最大允许充电电流";
CM_ SG_ 2335829655 M2P_PermitMaxDisCharge_I_B8_07 "汇流排8最大允许放电电流";
CM_ SG_ 2335829656 M2P_Measure_Vol_B8_08 "汇流排8所有高压在线电柜外侧电压平均值    ";
CM_ SG_ 2335829656 M2P_Current_B8_08 "汇流排8所有电柜电流累加和";
CM_ SG_ 2335829656 M2P_PermitMaxCharge_I_B8_08 "汇流排8最大允许充电电流";
CM_ SG_ 2335829656 M2P_PermitMaxDisCharge_I_B8_08 "汇流排8最大允许放电电流";
CM_ SG_ 2335829657 M2P_Measure_Vol_B8_09 "汇流排8所有高压在线电柜外侧电压平均值    ";
CM_ SG_ 2335829657 M2P_Current_B8_09 "汇流排8所有电柜电流累加和";
CM_ SG_ 2335829657 M2P_PermitMaxCharge_I_B8_09 "汇流排8最大允许充电电流";
CM_ SG_ 2335829657 M2P_PermitMaxDisCharge_I_B8_09 "汇流排8最大允许放电电流";
CM_ SG_ 2335829658 M2P_Measure_Vol_B8_10 "汇流排8所有高压在线电柜外侧电压平均值    ";
CM_ SG_ 2335829658 M2P_Current_B8_10 "汇流排8所有电柜电流累加和";
CM_ SG_ 2335829658 M2P_PermitMaxCharge_I_B8_10 "汇流排8最大允许充电电流";
CM_ SG_ 2335829658 M2P_PermitMaxDisCharge_I_B8_10 "汇流排8最大允许放电电流";
CM_ SG_ 2335829659 M2P_Measure_Vol_B8_11 "汇流排8所有高压在线电柜外侧电压平均值    ";
CM_ SG_ 2335829659 M2P_Current_B8_11 "汇流排8所有电柜电流累加和";
CM_ SG_ 2335829659 M2P_PermitMaxCharge_I_B8_11 "汇流排8最大允许充电电流";
CM_ SG_ 2335829659 M2P_PermitMaxDisCharge_I_B8_11 "汇流排8最大允许放电电流";
CM_ SG_ 2335829660 M2P_Measure_Vol_B8_12 "汇流排8所有高压在线电柜外侧电压平均值    ";
CM_ SG_ 2335829660 M2P_Current_B8_12 "汇流排8所有电柜电流累加和";
CM_ SG_ 2335829660 M2P_PermitMaxCharge_I_B8_12 "汇流排8最大允许充电电流";
CM_ SG_ 2335829660 M2P_PermitMaxDisCharge_I_B8_12 "汇流排8最大允许放电电流";
CM_ SG_ 2335829661 M2P_Measure_Vol_B8_13 "汇流排8所有高压在线电柜外侧电压平均值    ";
CM_ SG_ 2335829661 M2P_Current_B8_13 "汇流排8所有电柜电流累加和";
CM_ SG_ 2335829661 M2P_PermitMaxCharge_I_B8_13 "汇流排8最大允许充电电流";
CM_ SG_ 2335829661 M2P_PermitMaxDisCharge_I_B8_13 "汇流排8最大允许放电电流";
CM_ SG_ 2335829662 M2P_Measure_Vol_B8_14 "汇流排8所有高压在线电柜外侧电压平均值    ";
CM_ SG_ 2335829662 M2P_Current_B8_14 "汇流排8所有电柜电流累加和";
CM_ SG_ 2335829662 M2P_PermitMaxCharge_I_B8_14 "汇流排8最大允许充电电流";
CM_ SG_ 2335829662 M2P_PermitMaxDisCharge_I_B8_14 "汇流排8最大允许放电电流";
CM_ SG_ 2335829663 M2P_Measure_Vol_B8_15 "汇流排8所有高压在线电柜外侧电压平均值    ";
CM_ SG_ 2335829663 M2P_Current_B8_15 "汇流排8所有电柜电流累加和";
CM_ SG_ 2335829663 M2P_PermitMaxCharge_I_B8_15 "汇流排8最大允许充电电流";
CM_ SG_ 2335829663 M2P_PermitMaxDisCharge_I_B8_15 "汇流排8最大允许放电电流";
CM_ SG_ 2335829664 M2P_Measure_Vol_B8_16 "汇流排8所有高压在线电柜外侧电压平均值    ";
CM_ SG_ 2335829664 M2P_Current_B8_16 "汇流排8所有电柜电流累加和";
CM_ SG_ 2335829664 M2P_PermitMaxCharge_I_B8_16 "汇流排8最大允许充电电流";
CM_ SG_ 2335829664 M2P_PermitMaxDisCharge_I_B8_16 "汇流排8最大允许放电电流";
CM_ SG_ 2335829665 M2P_Measure_Vol_B8_17 "汇流排8所有高压在线电柜外侧电压平均值    ";
CM_ SG_ 2335829665 M2P_Current_B8_17 "汇流排8所有电柜电流累加和";
CM_ SG_ 2335829665 M2P_PermitMaxCharge_I_B8_17 "汇流排8最大允许充电电流";
CM_ SG_ 2335829665 M2P_PermitMaxDisCharge_I_B8_17 "汇流排8最大允许放电电流";
CM_ SG_ 2335829666 M2P_Measure_Vol_B8_18 "汇流排8所有高压在线电柜外侧电压平均值    ";
CM_ SG_ 2335829666 M2P_Current_B8_18 "汇流排8所有电柜电流累加和";
CM_ SG_ 2335829666 M2P_PermitMaxCharge_I_B8_18 "汇流排8最大允许充电电流";
CM_ SG_ 2335829666 M2P_PermitMaxDisCharge_I_B8_18 "汇流排8最大允许放电电流";
CM_ SG_ 2335829667 M2P_Measure_Vol_B8_19 "汇流排8所有高压在线电柜外侧电压平均值    ";
CM_ SG_ 2335829667 M2P_Current_B8_19 "汇流排8所有电柜电流累加和";
CM_ SG_ 2335829667 M2P_PermitMaxCharge_I_B8_19 "汇流排8最大允许充电电流";
CM_ SG_ 2335829667 M2P_PermitMaxDisCharge_I_B8_19 "汇流排8最大允许放电电流";
CM_ SG_ 2335829668 M2P_Measure_Vol_B8_20 "汇流排8所有高压在线电柜外侧电压平均值    ";
CM_ SG_ 2335829668 M2P_Current_B8_20 "汇流排8所有电柜电流累加和";
CM_ SG_ 2335829668 M2P_PermitMaxCharge_I_B8_20 "汇流排8最大允许充电电流";
CM_ SG_ 2335829668 M2P_PermitMaxDisCharge_I_B8_20 "汇流排8最大允许放电电流";
CM_ SG_ 2335829669 M2P_Measure_Vol_B8_21 "汇流排8所有高压在线电柜外侧电压平均值    ";
CM_ SG_ 2335829669 M2P_Current_B8_21 "汇流排8所有电柜电流累加和";
CM_ SG_ 2335829669 M2P_PermitMaxCharge_I_B8_21 "汇流排8最大允许充电电流";
CM_ SG_ 2335829669 M2P_PermitMaxDisCharge_I_B8_21 "汇流排8最大允许放电电流";
CM_ SG_ 2335829670 M2P_Measure_Vol_B8_22 "汇流排8所有高压在线电柜外侧电压平均值    ";
CM_ SG_ 2335829670 M2P_Current_B8_22 "汇流排8所有电柜电流累加和";
CM_ SG_ 2335829670 M2P_PermitMaxCharge_I_B8_22 "汇流排8最大允许充电电流";
CM_ SG_ 2335829670 M2P_PermitMaxDisCharge_I_B8_22 "汇流排8最大允许放电电流";
CM_ SG_ 2335829671 M2P_Measure_Vol_B8_23 "汇流排8所有高压在线电柜外侧电压平均值    ";
CM_ SG_ 2335829671 M2P_Current_B8_23 "汇流排8所有电柜电流累加和";
CM_ SG_ 2335829671 M2P_PermitMaxCharge_I_B8_23 "汇流排8最大允许充电电流";
CM_ SG_ 2335829671 M2P_PermitMaxDisCharge_I_B8_23 "汇流排8最大允许放电电流";
CM_ SG_ 2335829672 M2P_Measure_Vol_B8_24 "汇流排8所有高压在线电柜外侧电压平均值    ";
CM_ SG_ 2335829672 M2P_Current_B8_24 "汇流排8所有电柜电流累加和";
CM_ SG_ 2335829672 M2P_PermitMaxCharge_I_B8_24 "汇流排8最大允许充电电流";
CM_ SG_ 2335829672 M2P_PermitMaxDisCharge_I_B8_24 "汇流排8最大允许放电电流";
CM_ SG_ 2335829673 M2P_Measure_Vol_B8_25 "汇流排8所有高压在线电柜外侧电压平均值    ";
CM_ SG_ 2335829673 M2P_Current_B8_25 "汇流排8所有电柜电流累加和";
CM_ SG_ 2335829673 M2P_PermitMaxCharge_I_B8_25 "汇流排8最大允许充电电流";
CM_ SG_ 2335829673 M2P_PermitMaxDisCharge_I_B8_25 "汇流排8最大允许放电电流";
CM_ SG_ 2335829674 M2P_Measure_Vol_B8_26 "汇流排8所有高压在线电柜外侧电压平均值    ";
CM_ SG_ 2335829674 M2P_Current_B8_26 "汇流排8所有电柜电流累加和";
CM_ SG_ 2335829674 M2P_PermitMaxCharge_I_B8_26 "汇流排8最大允许充电电流";
CM_ SG_ 2335829674 M2P_PermitMaxDisCharge_I_B8_26 "汇流排8最大允许放电电流";
CM_ SG_ 2335829675 M2P_Measure_Vol_B8_27 "汇流排8所有高压在线电柜外侧电压平均值    ";
CM_ SG_ 2335829675 M2P_Current_B8_27 "汇流排8所有电柜电流累加和";
CM_ SG_ 2335829675 M2P_PermitMaxCharge_I_B8_27 "汇流排8最大允许充电电流";
CM_ SG_ 2335829675 M2P_PermitMaxDisCharge_I_B8_27 "汇流排8最大允许放电电流";
CM_ SG_ 2335829676 M2P_Measure_Vol_B8_28 "汇流排8所有高压在线电柜外侧电压平均值    ";
CM_ SG_ 2335829676 M2P_Current_B8_28 "汇流排8所有电柜电流累加和";
CM_ SG_ 2335829676 M2P_PermitMaxCharge_I_B8_28 "汇流排8最大允许充电电流";
CM_ SG_ 2335829676 M2P_PermitMaxDisCharge_I_B8_28 "汇流排8最大允许放电电流";
CM_ SG_ 2335829677 M2P_Measure_Vol_B8_29 "汇流排8所有高压在线电柜外侧电压平均值    ";
CM_ SG_ 2335829677 M2P_Current_B8_29 "汇流排8所有电柜电流累加和";
CM_ SG_ 2335829677 M2P_PermitMaxCharge_I_B8_29 "汇流排8最大允许充电电流";
CM_ SG_ 2335829677 M2P_PermitMaxDisCharge_I_B8_29 "汇流排8最大允许放电电流";
CM_ SG_ 2335829678 M2P_Measure_Vol_B8_30 "汇流排8所有高压在线电柜外侧电压平均值    ";
CM_ SG_ 2335829678 M2P_Current_B8_30 "汇流排8所有电柜电流累加和";
CM_ SG_ 2335829678 M2P_PermitMaxCharge_I_B8_30 "汇流排8最大允许充电电流";
CM_ SG_ 2335829678 M2P_PermitMaxDisCharge_I_B8_30 "汇流排8最大允许放电电流";
CM_ SG_ 2335829679 M2P_Measure_Vol_B8_31 "汇流排8所有高压在线电柜外侧电压平均值    ";
CM_ SG_ 2335829679 M2P_Current_B8_31 "汇流排8所有电柜电流累加和";
CM_ SG_ 2335829679 M2P_PermitMaxCharge_I_B8_31 "汇流排8最大允许充电电流";
CM_ SG_ 2335829679 M2P_PermitMaxDisCharge_I_B8_31 "汇流排8最大允许放电电流";
CM_ SG_ 2335895185 M2P_PermitMaxVolt_B8_01 "汇流排8最高允许充电电压 （配置量）";
CM_ SG_ 2335895185 M2P_PermitMinVolt_B8_01 "汇流排8最低允许放电电压 （配置量）";
CM_ SG_ 2335895185 M2P_PermitMaxPow_Chg_B8_01 "汇流排8最大允许充电功率";
CM_ SG_ 2335895185 M2P_PermitMaxPow_DisChg_B8_01 "汇流排8最大允许放电功率";
CM_ SG_ 2335895186 M2P_PermitMaxVolt_B8_02 "汇流排8最高允许充电电压 （配置量）";
CM_ SG_ 2335895186 M2P_PermitMinVolt_B8_02 "汇流排8最低允许放电电压 （配置量）";
CM_ SG_ 2335895186 M2P_PermitMaxPow_Chg_B8_02 "汇流排8最大允许充电功率";
CM_ SG_ 2335895186 M2P_PermitMaxPow_DisChg_B8_02 "汇流排8最大允许放电功率";
CM_ SG_ 2335895187 M2P_PermitMaxVolt_B8_03 "汇流排8最高允许充电电压 （配置量）";
CM_ SG_ 2335895187 M2P_PermitMinVolt_B8_03 "汇流排8最低允许放电电压 （配置量）";
CM_ SG_ 2335895187 M2P_PermitMaxPow_Chg_B8_03 "汇流排8最大允许充电功率";
CM_ SG_ 2335895187 M2P_PermitMaxPow_DisChg_B8_03 "汇流排8最大允许放电功率";
CM_ SG_ 2335895188 M2P_PermitMaxVolt_B8_04 "汇流排8最高允许充电电压 （配置量）";
CM_ SG_ 2335895188 M2P_PermitMinVolt_B8_04 "汇流排8最低允许放电电压 （配置量）";
CM_ SG_ 2335895188 M2P_PermitMaxPow_Chg_B8_04 "汇流排8最大允许充电功率";
CM_ SG_ 2335895188 M2P_PermitMaxPow_DisChg_B8_04 "汇流排8最大允许放电功率";
CM_ SG_ 2335895189 M2P_PermitMaxVolt_B8_05 "汇流排8最高允许充电电压 （配置量）";
CM_ SG_ 2335895189 M2P_PermitMinVolt_B8_05 "汇流排8最低允许放电电压 （配置量）";
CM_ SG_ 2335895189 M2P_PermitMaxPow_Chg_B8_05 "汇流排8最大允许充电功率";
CM_ SG_ 2335895189 M2P_PermitMaxPow_DisChg_B8_05 "汇流排8最大允许放电功率";
CM_ SG_ 2335895190 M2P_PermitMaxVolt_B8_06 "汇流排8最高允许充电电压 （配置量）";
CM_ SG_ 2335895190 M2P_PermitMinVolt_B8_06 "汇流排8最低允许放电电压 （配置量）";
CM_ SG_ 2335895190 M2P_PermitMaxPow_Chg_B8_06 "汇流排8最大允许充电功率";
CM_ SG_ 2335895190 M2P_PermitMaxPow_DisChg_B8_06 "汇流排8最大允许放电功率";
CM_ SG_ 2335895191 M2P_PermitMaxVolt_B8_07 "汇流排8最高允许充电电压 （配置量）";
CM_ SG_ 2335895191 M2P_PermitMinVolt_B8_07 "汇流排8最低允许放电电压 （配置量）";
CM_ SG_ 2335895191 M2P_PermitMaxPow_Chg_B8_07 "汇流排8最大允许充电功率";
CM_ SG_ 2335895191 M2P_PermitMaxPow_DisChg_B8_07 "汇流排8最大允许放电功率";
CM_ SG_ 2335895192 M2P_PermitMaxVolt_B8_08 "汇流排8最高允许充电电压 （配置量）";
CM_ SG_ 2335895192 M2P_PermitMinVolt_B8_08 "汇流排8最低允许放电电压 （配置量）";
CM_ SG_ 2335895192 M2P_PermitMaxPow_Chg_B8_08 "汇流排8最大允许充电功率";
CM_ SG_ 2335895192 M2P_PermitMaxPow_DisChg_B8_08 "汇流排8最大允许放电功率";
CM_ SG_ 2335895193 M2P_PermitMaxVolt_B8_09 "汇流排8最高允许充电电压 （配置量）";
CM_ SG_ 2335895193 M2P_PermitMinVolt_B8_09 "汇流排8最低允许放电电压 （配置量）";
CM_ SG_ 2335895193 M2P_PermitMaxPow_Chg_B8_09 "汇流排8最大允许充电功率";
CM_ SG_ 2335895193 M2P_PermitMaxPow_DisChg_B8_09 "汇流排8最大允许放电功率";
CM_ SG_ 2335895194 M2P_PermitMaxVolt_B8_10 "汇流排8最高允许充电电压 （配置量）";
CM_ SG_ 2335895194 M2P_PermitMinVolt_B8_10 "汇流排8最低允许放电电压 （配置量）";
CM_ SG_ 2335895194 M2P_PermitMaxPow_Chg_B8_10 "汇流排8最大允许充电功率";
CM_ SG_ 2335895194 M2P_PermitMaxPow_DisChg_B8_10 "汇流排8最大允许放电功率";
CM_ SG_ 2335895195 M2P_PermitMaxVolt_B8_11 "汇流排8最高允许充电电压 （配置量）";
CM_ SG_ 2335895195 M2P_PermitMinVolt_B8_11 "汇流排8最低允许放电电压 （配置量）";
CM_ SG_ 2335895195 M2P_PermitMaxPow_Chg_B8_11 "汇流排8最大允许充电功率";
CM_ SG_ 2335895195 M2P_PermitMaxPow_DisChg_B8_11 "汇流排8最大允许放电功率";
CM_ SG_ 2335895196 M2P_PermitMaxVolt_B8_12 "汇流排8最高允许充电电压 （配置量）";
CM_ SG_ 2335895196 M2P_PermitMinVolt_B8_12 "汇流排8最低允许放电电压 （配置量）";
CM_ SG_ 2335895196 M2P_PermitMaxPow_Chg_B8_12 "汇流排8最大允许充电功率";
CM_ SG_ 2335895196 M2P_PermitMaxPow_DisChg_B8_12 "汇流排8最大允许放电功率";
CM_ SG_ 2335895197 M2P_PermitMaxVolt_B8_13 "汇流排8最高允许充电电压 （配置量）";
CM_ SG_ 2335895197 M2P_PermitMinVolt_B8_13 "汇流排8最低允许放电电压 （配置量）";
CM_ SG_ 2335895197 M2P_PermitMaxPow_Chg_B8_13 "汇流排8最大允许充电功率";
CM_ SG_ 2335895197 M2P_PermitMaxPow_DisChg_B8_13 "汇流排8最大允许放电功率";
CM_ SG_ 2335895198 M2P_PermitMaxVolt_B8_14 "汇流排8最高允许充电电压 （配置量）";
CM_ SG_ 2335895198 M2P_PermitMinVolt_B8_14 "汇流排8最低允许放电电压 （配置量）";
CM_ SG_ 2335895198 M2P_PermitMaxPow_Chg_B8_14 "汇流排8最大允许充电功率";
CM_ SG_ 2335895198 M2P_PermitMaxPow_DisChg_B8_14 "汇流排8最大允许放电功率";
CM_ SG_ 2335895199 M2P_PermitMaxVolt_B8_15 "汇流排8最高允许充电电压 （配置量）";
CM_ SG_ 2335895199 M2P_PermitMinVolt_B8_15 "汇流排8最低允许放电电压 （配置量）";
CM_ SG_ 2335895199 M2P_PermitMaxPow_Chg_B8_15 "汇流排8最大允许充电功率";
CM_ SG_ 2335895199 M2P_PermitMaxPow_DisChg_B8_15 "汇流排8最大允许放电功率";
CM_ SG_ 2335895200 M2P_PermitMaxVolt_B8_16 "汇流排8最高允许充电电压 （配置量）";
CM_ SG_ 2335895200 M2P_PermitMinVolt_B8_16 "汇流排8最低允许放电电压 （配置量）";
CM_ SG_ 2335895200 M2P_PermitMaxPow_Chg_B8_16 "汇流排8最大允许充电功率";
CM_ SG_ 2335895200 M2P_PermitMaxPow_DisChg_B8_16 "汇流排8最大允许放电功率";
VAL_ 2335305382 M2P_SysremEngy_Chg_B6_22 65535 "Invalid" ;
VAL_ 2335305382 M2P_SysremEngy_DisChg_B6_22 65535 "Invalid" ;
VAL_ 2335305383 M2P_SysremEngy_Chg_B6_23 65535 "Invalid" ;
VAL_ 2335305383 M2P_SysremEngy_DisChg_B6_23 65535 "Invalid" ;
VAL_ 2335305384 M2P_SysremEngy_Chg_B6_24 65535 "Invalid" ;
VAL_ 2335305384 M2P_SysremEngy_DisChg_B6_24 65535 "Invalid" ;
VAL_ 2335305385 M2P_SysremEngy_Chg_B6_25 65535 "Invalid" ;
VAL_ 2335305385 M2P_SysremEngy_DisChg_B6_25 65535 "Invalid" ;
VAL_ 2335305386 M2P_SysremEngy_Chg_B6_26 65535 "Invalid" ;
VAL_ 2335305386 M2P_SysremEngy_DisChg_B6_26 65535 "Invalid" ;
VAL_ 2335305387 M2P_SysremEngy_Chg_B6_27 65535 "Invalid" ;
VAL_ 2335305387 M2P_SysremEngy_DisChg_B6_27 65535 "Invalid" ;
VAL_ 2335305388 M2P_SysremEngy_Chg_B6_28 65535 "Invalid" ;
VAL_ 2335305388 M2P_SysremEngy_DisChg_B6_28 65535 "Invalid" ;
VAL_ 2335305389 M2P_SysremEngy_Chg_B6_29 65535 "Invalid" ;
VAL_ 2335305389 M2P_SysremEngy_DisChg_B6_29 65535 "Invalid" ;
VAL_ 2335305390 M2P_SysremEngy_Chg_B6_30 65535 "Invalid" ;
VAL_ 2335305390 M2P_SysremEngy_DisChg_B6_30 65535 "Invalid" ;
VAL_ 2335305391 M2P_SysremEngy_Chg_B6_31 65535 "Invalid" ;
VAL_ 2335305391 M2P_SysremEngy_DisChg_B6_31 65535 "Invalid" ;
VAL_ 2335370897 M2P_BMS_Status_B6 0 "初始化状态" 1 "非满充满放状态" 2 "满充状态" 3 "满放状态" ;
VAL_ 2335370897 M2P_SOC_B6 1023 "Null" ;
VAL_ 2335370897 M2P_SOH_B6 255 "Null" ;
VAL_ 2335370898 M2P_BMS_Status_B6 0 "初始化状态" 1 "非满充满放状态" 2 "满充状态" 3 "满放状态" ;
VAL_ 2335370898 M2P_SOC_B6 1023 "Null" ;
VAL_ 2335370898 M2P_SOH_B6 255 "Null" ;
VAL_ 2335370899 M2P_BMS_Status_B6 0 "初始化状态" 1 "非满充满放状态" 2 "满充状态" 3 "满放状态" ;
VAL_ 2335370899 M2P_SOC_B6 1023 "Null" ;
VAL_ 2335370899 M2P_SOH_B6 255 "Null" ;
VAL_ 2335370900 M2P_BMS_Status_B6 0 "初始化状态" 1 "非满充满放状态" 2 "满充状态" 3 "满放状态" ;
VAL_ 2335370900 M2P_SOC_B6 1023 "Null" ;
VAL_ 2335370900 M2P_SOH_B6 255 "Null" ;
VAL_ 2335370901 M2P_BMS_Status_B6 0 "初始化状态" 1 "非满充满放状态" 2 "满充状态" 3 "满放状态" ;
VAL_ 2335370901 M2P_SOC_B6 1023 "Null" ;
VAL_ 2335370901 M2P_SOH_B6 255 "Null" ;
VAL_ 2335370902 M2P_BMS_Status_B6 0 "初始化状态" 1 "非满充满放状态" 2 "满充状态" 3 "满放状态" ;
VAL_ 2335370902 M2P_SOC_B6 1023 "Null" ;
VAL_ 2335370902 M2P_SOH_B6 255 "Null" ;
VAL_ 2335370903 M2P_BMS_Status_B6 0 "初始化状态" 1 "非满充满放状态" 2 "满充状态" 3 "满放状态" ;
VAL_ 2335370903 M2P_SOC_B6 1023 "Null" ;
VAL_ 2335370903 M2P_SOH_B6 255 "Null" ;
VAL_ 2335370904 M2P_BMS_Status_B6 0 "初始化状态" 1 "非满充满放状态" 2 "满充状态" 3 "满放状态" ;
VAL_ 2335370904 M2P_SOC_B6 1023 "Null" ;
VAL_ 2335370904 M2P_SOH_B6 255 "Null" ;
VAL_ 2335370905 M2P_BMS_Status_B6 0 "初始化状态" 1 "非满充满放状态" 2 "满充状态" 3 "满放状态" ;
VAL_ 2335370905 M2P_SOC_B6 1023 "Null" ;
VAL_ 2335370905 M2P_SOH_B6 255 "Null" ;
VAL_ 2335370906 M2P_BMS_Status_B6 0 "初始化状态" 1 "非满充满放状态" 2 "满充状态" 3 "满放状态" ;
VAL_ 2335370906 M2P_SOC_B6 1023 "Null" ;
VAL_ 2335370906 M2P_SOH_B6 255 "Null" ;
VAL_ 2335370907 M2P_BMS_Status_B6 0 "初始化状态" 1 "非满充满放状态" 2 "满充状态" 3 "满放状态" ;
VAL_ 2335370907 M2P_SOC_B6 1023 "Null" ;
VAL_ 2335370907 M2P_SOH_B6 255 "Null" ;
VAL_ 2335370908 M2P_BMS_Status_B6 0 "初始化状态" 1 "非满充满放状态" 2 "满充状态" 3 "满放状态" ;
VAL_ 2335370908 M2P_SOC_B6 1023 "Null" ;
VAL_ 2335370908 M2P_SOH_B6 255 "Null" ;
VAL_ 2335370909 M2P_BMS_Status_B6 0 "初始化状态" 1 "非满充满放状态" 2 "满充状态" 3 "满放状态" ;
VAL_ 2335370909 M2P_SOC_B6 1023 "Null" ;
VAL_ 2335370909 M2P_SOH_B6 255 "Null" ;
VAL_ 2335370910 M2P_BMS_Status_B6 0 "初始化状态" 1 "非满充满放状态" 2 "满充状态" 3 "满放状态" ;
VAL_ 2335370910 M2P_SOC_B6 1023 "Null" ;
VAL_ 2335370910 M2P_SOH_B6 255 "Null" ;
VAL_ 2335370911 M2P_BMS_Status_B6 0 "初始化状态" 1 "非满充满放状态" 2 "满充状态" 3 "满放状态" ;
VAL_ 2335370911 M2P_SOC_B6 1023 "Null" ;
VAL_ 2335370911 M2P_SOH_B6 255 "Null" ;
VAL_ 2335370912 M2P_BMS_Status_B6 0 "初始化状态" 1 "非满充满放状态" 2 "满充状态" 3 "满放状态" ;
VAL_ 2335370912 M2P_SOC_B6 1023 "Null" ;
VAL_ 2335370912 M2P_SOH_B6 255 "Null" ;
VAL_ 2335370913 M2P_BMS_Status_B6 0 "初始化状态" 1 "非满充满放状态" 2 "满充状态" 3 "满放状态" ;
VAL_ 2335370913 M2P_SOC_B6 1023 "Null" ;
VAL_ 2335370913 M2P_SOH_B6 255 "Null" ;
VAL_ 2335370914 M2P_BMS_Status_B6 0 "初始化状态" 1 "非满充满放状态" 2 "满充状态" 3 "满放状态" ;
VAL_ 2335370914 M2P_SOC_B6 1023 "Null" ;
VAL_ 2335370914 M2P_SOH_B6 255 "Null" ;
VAL_ 2335370915 M2P_BMS_Status_B6 0 "初始化状态" 1 "非满充满放状态" 2 "满充状态" 3 "满放状态" ;
VAL_ 2335370915 M2P_SOC_B6 1023 "Null" ;
VAL_ 2335370915 M2P_SOH_B6 255 "Null" ;
VAL_ 2335370916 M2P_BMS_Status_B6 0 "初始化状态" 1 "非满充满放状态" 2 "满充状态" 3 "满放状态" ;
VAL_ 2335370916 M2P_SOC_B6 1023 "Null" ;
VAL_ 2335370916 M2P_SOH_B6 255 "Null" ;
VAL_ 2335370917 M2P_BMS_Status_B6 0 "初始化状态" 1 "非满充满放状态" 2 "满充状态" 3 "满放状态" ;
VAL_ 2335370917 M2P_SOC_B6 1023 "Null" ;
VAL_ 2335370917 M2P_SOH_B6 255 "Null" ;
VAL_ 2335370918 M2P_BMS_Status_B6 0 "初始化状态" 1 "非满充满放状态" 2 "满充状态" 3 "满放状态" ;
VAL_ 2335370918 M2P_SOC_B6 1023 "Null" ;
VAL_ 2335370918 M2P_SOH_B6 255 "Null" ;
VAL_ 2335370919 M2P_BMS_Status_B6 0 "初始化状态" 1 "非满充满放状态" 2 "满充状态" 3 "满放状态" ;
VAL_ 2335370919 M2P_SOC_B6 1023 "Null" ;
VAL_ 2335370919 M2P_SOH_B6 255 "Null" ;
VAL_ 2335370920 M2P_BMS_Status_B6 0 "初始化状态" 1 "非满充满放状态" 2 "满充状态" 3 "满放状态" ;
VAL_ 2335370920 M2P_SOC_B6 1023 "Null" ;
VAL_ 2335370920 M2P_SOH_B6 255 "Null" ;
VAL_ 2335370921 M2P_BMS_Status_B6 0 "初始化状态" 1 "非满充满放状态" 2 "满充状态" 3 "满放状态" ;
VAL_ 2335370921 M2P_SOC_B6 1023 "Null" ;
VAL_ 2335370921 M2P_SOH_B6 255 "Null" ;
VAL_ 2335370922 M2P_BMS_Status_B6 0 "初始化状态" 1 "非满充满放状态" 2 "满充状态" 3 "满放状态" ;
VAL_ 2335370922 M2P_SOC_B6 1023 "Null" ;
VAL_ 2335370922 M2P_SOH_B6 255 "Null" ;
VAL_ 2335370923 M2P_BMS_Status_B6 0 "初始化状态" 1 "非满充满放状态" 2 "满充状态" 3 "满放状态" ;
VAL_ 2335370923 M2P_SOC_B6 1023 "Null" ;
VAL_ 2335370923 M2P_SOH_B6 255 "Null" ;
VAL_ 2335370924 M2P_BMS_Status_B6 0 "初始化状态" 1 "非满充满放状态" 2 "满充状态" 3 "满放状态" ;
VAL_ 2335370924 M2P_SOC_B6 1023 "Null" ;
VAL_ 2335370924 M2P_SOH_B6 255 "Null" ;
VAL_ 2335370925 M2P_BMS_Status_B6 0 "初始化状态" 1 "非满充满放状态" 2 "满充状态" 3 "满放状态" ;
VAL_ 2335370925 M2P_SOC_B6 1023 "Null" ;
VAL_ 2335370925 M2P_SOH_B6 255 "Null" ;
VAL_ 2335370926 M2P_BMS_Status_B6 0 "初始化状态" 1 "非满充满放状态" 2 "满充状态" 3 "满放状态" ;
VAL_ 2335370926 M2P_SOC_B6 1023 "Null" ;
VAL_ 2335370926 M2P_SOH_B6 255 "Null" ;
VAL_ 2335370927 M2P_BMS_Status_B6 0 "初始化状态" 1 "非满充满放状态" 2 "满充状态" 3 "满放状态" ;
VAL_ 2335370927 M2P_SOC_B6 1023 "Null" ;
VAL_ 2335370927 M2P_SOH_B6 255 "Null" ;
VAL_ 2335436433 M2P_SOE_Charge_B6 1023 "Null" ;
VAL_ 2335436433 M2P_SOE_Discharge_B6 1023 "Null" ;
VAL_ 2335436434 M2P_SOE_Charge_B6 1023 "Null" ;
VAL_ 2335436434 M2P_SOE_Discharge_B6 1023 "Null" ;
VAL_ 2335436435 M2P_SOE_Charge_B6 1023 "Null" ;
VAL_ 2335436435 M2P_SOE_Discharge_B6 1023 "Null" ;
VAL_ 2335436436 M2P_SOE_Charge_B6 1023 "Null" ;
VAL_ 2335436436 M2P_SOE_Discharge_B6 1023 "Null" ;
VAL_ 2335436437 M2P_SOE_Charge_B6 1023 "Null" ;
VAL_ 2335436437 M2P_SOE_Discharge_B6 1023 "Null" ;
VAL_ 2335436438 M2P_SOE_Charge_B6 1023 "Null" ;
VAL_ 2335436438 M2P_SOE_Discharge_B6 1023 "Null" ;
VAL_ 2335436439 M2P_SOE_Charge_B6 1023 "Null" ;
VAL_ 2335436439 M2P_SOE_Discharge_B6 1023 "Null" ;
VAL_ 2335436440 M2P_SOE_Charge_B6 1023 "Null" ;
VAL_ 2335436440 M2P_SOE_Discharge_B6 1023 "Null" ;
VAL_ 2335436441 M2P_SOE_Charge_B6 1023 "Null" ;
VAL_ 2335436441 M2P_SOE_Discharge_B6 1023 "Null" ;
VAL_ 2335436442 M2P_SOE_Charge_B6 1023 "Null" ;
VAL_ 2335436442 M2P_SOE_Discharge_B6 1023 "Null" ;
VAL_ 2335436443 M2P_SOE_Charge_B6 1023 "Null" ;
VAL_ 2335436443 M2P_SOE_Discharge_B6 1023 "Null" ;
VAL_ 2335436444 M2P_SOE_Charge_B6 1023 "Null" ;
VAL_ 2335436444 M2P_SOE_Discharge_B6 1023 "Null" ;
VAL_ 2335436445 M2P_SOE_Charge_B6 1023 "Null" ;
VAL_ 2335436445 M2P_SOE_Discharge_B6 1023 "Null" ;
VAL_ 2335436446 M2P_SOE_Charge_B6 1023 "Null" ;
VAL_ 2335436446 M2P_SOE_Discharge_B6 1023 "Null" ;
VAL_ 2335436447 M2P_SOE_Charge_B6 1023 "Null" ;
VAL_ 2335436447 M2P_SOE_Discharge_B6 1023 "Null" ;
VAL_ 2335436448 M2P_SOE_Charge_B6 1023 "Null" ;
VAL_ 2335436448 M2P_SOE_Discharge_B6 1023 "Null" ;
VAL_ 2335436449 M2P_SOE_Charge_B6 1023 "Null" ;
VAL_ 2335436449 M2P_SOE_Discharge_B6 1023 "Null" ;
VAL_ 2335436450 M2P_SOE_Charge_B6 1023 "Null" ;
VAL_ 2335436450 M2P_SOE_Discharge_B6 1023 "Null" ;
VAL_ 2335436451 M2P_SOE_Charge_B6 1023 "Null" ;
VAL_ 2335436451 M2P_SOE_Discharge_B6 1023 "Null" ;
VAL_ 2335436452 M2P_SOE_Charge_B6 1023 "Null" ;
VAL_ 2335436452 M2P_SOE_Discharge_B6 1023 "Null" ;
VAL_ 2335436453 M2P_SOE_Charge_B6 1023 "Null" ;
VAL_ 2335436453 M2P_SOE_Discharge_B6 1023 "Null" ;
VAL_ 2335436454 M2P_SOE_Charge_B6 1023 "Null" ;
VAL_ 2335436454 M2P_SOE_Discharge_B6 1023 "Null" ;
VAL_ 2335436455 M2P_SOE_Charge_B6 1023 "Null" ;
VAL_ 2335436455 M2P_SOE_Discharge_B6 1023 "Null" ;
VAL_ 2335436456 M2P_SOE_Charge_B6 1023 "Null" ;
VAL_ 2335436456 M2P_SOE_Discharge_B6 1023 "Null" ;
VAL_ 2335436457 M2P_SOE_Charge_B6 1023 "Null" ;
VAL_ 2335436457 M2P_SOE_Discharge_B6 1023 "Null" ;
VAL_ 2335436458 M2P_SOE_Charge_B6 1023 "Null" ;
VAL_ 2335436458 M2P_SOE_Discharge_B6 1023 "Null" ;
VAL_ 2335436459 M2P_SOE_Charge_B6 1023 "Null" ;
VAL_ 2335436459 M2P_SOE_Discharge_B6 1023 "Null" ;
VAL_ 2335436460 M2P_SOE_Charge_B6 1023 "Null" ;
VAL_ 2335436460 M2P_SOE_Discharge_B6 1023 "Null" ;
VAL_ 2335436461 M2P_SOE_Charge_B6 1023 "Null" ;
VAL_ 2335436461 M2P_SOE_Discharge_B6 1023 "Null" ;
VAL_ 2335436462 M2P_SOE_Charge_B6 1023 "Null" ;
VAL_ 2335436462 M2P_SOE_Discharge_B6 1023 "Null" ;
VAL_ 2335436463 M2P_SOE_Charge_B6 1023 "Null" ;
VAL_ 2335436463 M2P_SOE_Discharge_B6 1023 "Null" ;
VAL_ 2335501969 M2P_Measure_Vol_B7_01 65535 "Invalid" ;
VAL_ 2335501969 M2P_Current_B7_01 65535 "Invalid" ;
VAL_ 2335501969 M2P_PermitMaxCharge_I_B7_01 65535 "Invalid" ;
VAL_ 2335501969 M2P_PermitMaxDisCharge_I_B7_01 65535 "Invalid" ;
VAL_ 2335501970 M2P_Measure_Vol_B7_02 65535 "Invalid" ;
VAL_ 2335501970 M2P_Current_B7_02 65535 "Invalid" ;
VAL_ 2335501970 M2P_PermitMaxCharge_I_B7_02 65535 "Invalid" ;
VAL_ 2335501970 M2P_PermitMaxDisCharge_I_B7_02 65535 "Invalid" ;
VAL_ 2335501971 M2P_Measure_Vol_B7_03 65535 "Invalid" ;
VAL_ 2335501971 M2P_Current_B7_03 65535 "Invalid" ;
VAL_ 2335501971 M2P_PermitMaxCharge_I_B7_03 65535 "Invalid" ;
VAL_ 2335501971 M2P_PermitMaxDisCharge_I_B7_03 65535 "Invalid" ;
VAL_ 2335501972 M2P_Measure_Vol_B7_04 65535 "Invalid" ;
VAL_ 2335501972 M2P_Current_B7_04 65535 "Invalid" ;
VAL_ 2335501972 M2P_PermitMaxCharge_I_B7_04 65535 "Invalid" ;
VAL_ 2335501972 M2P_PermitMaxDisCharge_I_B7_04 65535 "Invalid" ;
VAL_ 2335501973 M2P_Measure_Vol_B7_05 65535 "Invalid" ;
VAL_ 2335501973 M2P_Current_B7_05 65535 "Invalid" ;
VAL_ 2335501973 M2P_PermitMaxCharge_I_B7_05 65535 "Invalid" ;
VAL_ 2335501973 M2P_PermitMaxDisCharge_I_B7_05 65535 "Invalid" ;
VAL_ 2335501974 M2P_Measure_Vol_B7_06 65535 "Invalid" ;
VAL_ 2335501974 M2P_Current_B7_06 65535 "Invalid" ;
VAL_ 2335501974 M2P_PermitMaxCharge_I_B7_06 65535 "Invalid" ;
VAL_ 2335501974 M2P_PermitMaxDisCharge_I_B7_06 65535 "Invalid" ;
VAL_ 2335501975 M2P_Measure_Vol_B7_07 65535 "Invalid" ;
VAL_ 2335501975 M2P_Current_B7_07 65535 "Invalid" ;
VAL_ 2335501975 M2P_PermitMaxCharge_I_B7_07 65535 "Invalid" ;
VAL_ 2335501975 M2P_PermitMaxDisCharge_I_B7_07 65535 "Invalid" ;
VAL_ 2335501976 M2P_Measure_Vol_B7_08 65535 "Invalid" ;
VAL_ 2335501976 M2P_Current_B7_08 65535 "Invalid" ;
VAL_ 2335501976 M2P_PermitMaxCharge_I_B7_08 65535 "Invalid" ;
VAL_ 2335501976 M2P_PermitMaxDisCharge_I_B7_08 65535 "Invalid" ;
VAL_ 2335501977 M2P_Measure_Vol_B7_09 65535 "Invalid" ;
VAL_ 2335501977 M2P_Current_B7_09 65535 "Invalid" ;
VAL_ 2335501977 M2P_PermitMaxCharge_I_B7_09 65535 "Invalid" ;
VAL_ 2335501977 M2P_PermitMaxDisCharge_I_B7_09 65535 "Invalid" ;
VAL_ 2335501978 M2P_Measure_Vol_B7_10 65535 "Invalid" ;
VAL_ 2335501978 M2P_Current_B7_10 65535 "Invalid" ;
VAL_ 2335501978 M2P_PermitMaxCharge_I_B7_10 65535 "Invalid" ;
VAL_ 2335501978 M2P_PermitMaxDisCharge_I_B7_10 65535 "Invalid" ;
VAL_ 2335501979 M2P_Measure_Vol_B7_11 65535 "Invalid" ;
VAL_ 2335501979 M2P_Current_B7_11 65535 "Invalid" ;
VAL_ 2335501979 M2P_PermitMaxCharge_I_B7_11 65535 "Invalid" ;
VAL_ 2335501979 M2P_PermitMaxDisCharge_I_B7_11 65535 "Invalid" ;
VAL_ 2335501980 M2P_Measure_Vol_B7_12 65535 "Invalid" ;
VAL_ 2335501980 M2P_Current_B7_12 65535 "Invalid" ;
VAL_ 2335501980 M2P_PermitMaxCharge_I_B7_12 65535 "Invalid" ;
VAL_ 2335501980 M2P_PermitMaxDisCharge_I_B7_12 65535 "Invalid" ;
VAL_ 2335501981 M2P_Measure_Vol_B7_13 65535 "Invalid" ;
VAL_ 2335501981 M2P_Current_B7_13 65535 "Invalid" ;
VAL_ 2335501981 M2P_PermitMaxCharge_I_B7_13 65535 "Invalid" ;
VAL_ 2335501981 M2P_PermitMaxDisCharge_I_B7_13 65535 "Invalid" ;
VAL_ 2335501982 M2P_Measure_Vol_B7_14 65535 "Invalid" ;
VAL_ 2335501982 M2P_Current_B7_14 65535 "Invalid" ;
VAL_ 2335501982 M2P_PermitMaxCharge_I_B7_14 65535 "Invalid" ;
VAL_ 2335501982 M2P_PermitMaxDisCharge_I_B7_14 65535 "Invalid" ;
VAL_ 2335501983 M2P_Measure_Vol_B7_15 65535 "Invalid" ;
VAL_ 2335501983 M2P_Current_B7_15 65535 "Invalid" ;
VAL_ 2335501983 M2P_PermitMaxCharge_I_B7_15 65535 "Invalid" ;
VAL_ 2335501983 M2P_PermitMaxDisCharge_I_B7_15 65535 "Invalid" ;
VAL_ 2335501984 M2P_Measure_Vol_B7_16 65535 "Invalid" ;
VAL_ 2335501984 M2P_Current_B7_16 65535 "Invalid" ;
VAL_ 2335501984 M2P_PermitMaxCharge_I_B7_16 65535 "Invalid" ;
VAL_ 2335501984 M2P_PermitMaxDisCharge_I_B7_16 65535 "Invalid" ;
VAL_ 2335501985 M2P_Measure_Vol_B7_17 65535 "Invalid" ;
VAL_ 2335501985 M2P_Current_B7_17 65535 "Invalid" ;
VAL_ 2335501985 M2P_PermitMaxCharge_I_B7_17 65535 "Invalid" ;
VAL_ 2335501985 M2P_PermitMaxDisCharge_I_B7_17 65535 "Invalid" ;
VAL_ 2335501986 M2P_Measure_Vol_B7_18 65535 "Invalid" ;
VAL_ 2335501986 M2P_Current_B7_18 65535 "Invalid" ;
VAL_ 2335501986 M2P_PermitMaxCharge_I_B7_18 65535 "Invalid" ;
VAL_ 2335501986 M2P_PermitMaxDisCharge_I_B7_18 65535 "Invalid" ;
VAL_ 2335501987 M2P_Measure_Vol_B7_19 65535 "Invalid" ;
VAL_ 2335501987 M2P_Current_B7_19 65535 "Invalid" ;
VAL_ 2335501987 M2P_PermitMaxCharge_I_B7_19 65535 "Invalid" ;
VAL_ 2335501987 M2P_PermitMaxDisCharge_I_B7_19 65535 "Invalid" ;
VAL_ 2335501988 M2P_Measure_Vol_B7_20 65535 "Invalid" ;
VAL_ 2335501988 M2P_Current_B7_20 65535 "Invalid" ;
VAL_ 2335501988 M2P_PermitMaxCharge_I_B7_20 65535 "Invalid" ;
VAL_ 2335501988 M2P_PermitMaxDisCharge_I_B7_20 65535 "Invalid" ;
VAL_ 2335501989 M2P_Measure_Vol_B7_21 65535 "Invalid" ;
VAL_ 2335501989 M2P_Current_B7_21 65535 "Invalid" ;
VAL_ 2335501989 M2P_PermitMaxCharge_I_B7_21 65535 "Invalid" ;
VAL_ 2335501989 M2P_PermitMaxDisCharge_I_B7_21 65535 "Invalid" ;
VAL_ 2335501990 M2P_Measure_Vol_B7_22 65535 "Invalid" ;
VAL_ 2335501990 M2P_Current_B7_22 65535 "Invalid" ;
VAL_ 2335501990 M2P_PermitMaxCharge_I_B7_22 65535 "Invalid" ;
VAL_ 2335501990 M2P_PermitMaxDisCharge_I_B7_22 65535 "Invalid" ;
VAL_ 2335501991 M2P_Measure_Vol_B7_23 65535 "Invalid" ;
VAL_ 2335501991 M2P_Current_B7_23 65535 "Invalid" ;
VAL_ 2335501991 M2P_PermitMaxCharge_I_B7_23 65535 "Invalid" ;
VAL_ 2335501991 M2P_PermitMaxDisCharge_I_B7_23 65535 "Invalid" ;
VAL_ 2335501992 M2P_Measure_Vol_B7_24 65535 "Invalid" ;
VAL_ 2335501992 M2P_Current_B7_24 65535 "Invalid" ;
VAL_ 2335501992 M2P_PermitMaxCharge_I_B7_24 65535 "Invalid" ;
VAL_ 2335501992 M2P_PermitMaxDisCharge_I_B7_24 65535 "Invalid" ;
VAL_ 2335501993 M2P_Measure_Vol_B7_25 65535 "Invalid" ;
VAL_ 2335501993 M2P_Current_B7_25 65535 "Invalid" ;
VAL_ 2335501993 M2P_PermitMaxCharge_I_B7_25 65535 "Invalid" ;
VAL_ 2335501993 M2P_PermitMaxDisCharge_I_B7_25 65535 "Invalid" ;
VAL_ 2335501994 M2P_Measure_Vol_B7_26 65535 "Invalid" ;
VAL_ 2335501994 M2P_Current_B7_26 65535 "Invalid" ;
VAL_ 2335501994 M2P_PermitMaxCharge_I_B7_26 65535 "Invalid" ;
VAL_ 2335501994 M2P_PermitMaxDisCharge_I_B7_26 65535 "Invalid" ;
VAL_ 2335501995 M2P_Measure_Vol_B7_27 65535 "Invalid" ;
VAL_ 2335501995 M2P_Current_B7_27 65535 "Invalid" ;
VAL_ 2335501995 M2P_PermitMaxCharge_I_B7_27 65535 "Invalid" ;
VAL_ 2335501995 M2P_PermitMaxDisCharge_I_B7_27 65535 "Invalid" ;
VAL_ 2335501996 M2P_Measure_Vol_B7_28 65535 "Invalid" ;
VAL_ 2335501996 M2P_Current_B7_28 65535 "Invalid" ;
VAL_ 2335501996 M2P_PermitMaxCharge_I_B7_28 65535 "Invalid" ;
VAL_ 2335501996 M2P_PermitMaxDisCharge_I_B7_28 65535 "Invalid" ;
VAL_ 2335501997 M2P_Measure_Vol_B7_29 65535 "Invalid" ;
VAL_ 2335501997 M2P_Current_B7_29 65535 "Invalid" ;
VAL_ 2335501997 M2P_PermitMaxCharge_I_B7_29 65535 "Invalid" ;
VAL_ 2335501997 M2P_PermitMaxDisCharge_I_B7_29 65535 "Invalid" ;
VAL_ 2335501998 M2P_Measure_Vol_B7_30 65535 "Invalid" ;
VAL_ 2335501998 M2P_Current_B7_30 65535 "Invalid" ;
VAL_ 2335501998 M2P_PermitMaxCharge_I_B7_30 65535 "Invalid" ;
VAL_ 2335501998 M2P_PermitMaxDisCharge_I_B7_30 65535 "Invalid" ;
VAL_ 2335501999 M2P_Measure_Vol_B7_31 65535 "Invalid" ;
VAL_ 2335501999 M2P_Current_B7_31 65535 "Invalid" ;
VAL_ 2335501999 M2P_PermitMaxCharge_I_B7_31 65535 "Invalid" ;
VAL_ 2335501999 M2P_PermitMaxDisCharge_I_B7_31 65535 "Invalid" ;
VAL_ 2335633041 M2P_SysremEngy_Chg_B7_01 65535 "Invalid" ;
VAL_ 2335633041 M2P_SysremEngy_DisChg_B7_01 65535 "Invalid" ;
VAL_ 2335633042 M2P_SysremEngy_Chg_B7_02 65535 "Invalid" ;
VAL_ 2335633042 M2P_SysremEngy_DisChg_B7_02 65535 "Invalid" ;
VAL_ 2335633043 M2P_SysremEngy_Chg_B7_03 65535 "Invalid" ;
VAL_ 2335633043 M2P_SysremEngy_DisChg_B7_03 65535 "Invalid" ;
VAL_ 2335633044 M2P_SysremEngy_Chg_B7_04 65535 "Invalid" ;
VAL_ 2335633044 M2P_SysremEngy_DisChg_B7_04 65535 "Invalid" ;
VAL_ 2335633045 M2P_SysremEngy_Chg_B7_05 65535 "Invalid" ;
VAL_ 2335633045 M2P_SysremEngy_DisChg_B7_05 65535 "Invalid" ;
VAL_ 2335633046 M2P_SysremEngy_Chg_B7_06 65535 "Invalid" ;
VAL_ 2335633046 M2P_SysremEngy_DisChg_B7_06 65535 "Invalid" ;
VAL_ 2335633047 M2P_SysremEngy_Chg_B7_07 65535 "Invalid" ;
VAL_ 2335633047 M2P_SysremEngy_DisChg_B7_07 65535 "Invalid" ;
VAL_ 2335633048 M2P_SysremEngy_Chg_B7_08 65535 "Invalid" ;
VAL_ 2335633048 M2P_SysremEngy_DisChg_B7_08 65535 "Invalid" ;
VAL_ 2335633049 M2P_SysremEngy_Chg_B7_09 65535 "Invalid" ;
VAL_ 2335633049 M2P_SysremEngy_DisChg_B7_09 65535 "Invalid" ;
VAL_ 2335633050 M2P_SysremEngy_Chg_B7_10 65535 "Invalid" ;
VAL_ 2335633050 M2P_SysremEngy_DisChg_B7_10 65535 "Invalid" ;
VAL_ 2335633051 M2P_SysremEngy_Chg_B7_11 65535 "Invalid" ;
VAL_ 2335633051 M2P_SysremEngy_DisChg_B7_11 65535 "Invalid" ;
VAL_ 2335633052 M2P_SysremEngy_Chg_B7_12 65535 "Invalid" ;
VAL_ 2335633052 M2P_SysremEngy_DisChg_B7_12 65535 "Invalid" ;
VAL_ 2335633053 M2P_SysremEngy_Chg_B7_13 65535 "Invalid" ;
VAL_ 2335633053 M2P_SysremEngy_DisChg_B7_13 65535 "Invalid" ;
VAL_ 2335633054 M2P_SysremEngy_Chg_B7_14 65535 "Invalid" ;
VAL_ 2335633054 M2P_SysremEngy_DisChg_B7_14 65535 "Invalid" ;
VAL_ 2335633055 M2P_SysremEngy_Chg_B7_15 65535 "Invalid" ;
VAL_ 2335633055 M2P_SysremEngy_DisChg_B7_15 65535 "Invalid" ;
VAL_ 2335633056 M2P_SysremEngy_Chg_B7_16 65535 "Invalid" ;
VAL_ 2335633056 M2P_SysremEngy_DisChg_B7_16 65535 "Invalid" ;
VAL_ 2335633057 M2P_SysremEngy_Chg_B7_17 65535 "Invalid" ;
VAL_ 2335633057 M2P_SysremEngy_DisChg_B7_17 65535 "Invalid" ;
VAL_ 2335633058 M2P_SysremEngy_Chg_B7_18 65535 "Invalid" ;
VAL_ 2335633058 M2P_SysremEngy_DisChg_B7_18 65535 "Invalid" ;
VAL_ 2335633059 M2P_SysremEngy_Chg_B7_19 65535 "Invalid" ;
VAL_ 2335633059 M2P_SysremEngy_DisChg_B7_19 65535 "Invalid" ;
VAL_ 2335633060 M2P_SysremEngy_Chg_B7_20 65535 "Invalid" ;
VAL_ 2335633060 M2P_SysremEngy_DisChg_B7_20 65535 "Invalid" ;
VAL_ 2335633061 M2P_SysremEngy_Chg_B7_21 65535 "Invalid" ;
VAL_ 2335633061 M2P_SysremEngy_DisChg_B7_21 65535 "Invalid" ;
VAL_ 2335633062 M2P_SysremEngy_Chg_B7_22 65535 "Invalid" ;
VAL_ 2335633062 M2P_SysremEngy_DisChg_B7_22 65535 "Invalid" ;
VAL_ 2335633063 M2P_SysremEngy_Chg_B7_23 65535 "Invalid" ;
VAL_ 2335633063 M2P_SysremEngy_DisChg_B7_23 65535 "Invalid" ;
VAL_ 2335633064 M2P_SysremEngy_Chg_B7_24 65535 "Invalid" ;
VAL_ 2335633064 M2P_SysremEngy_DisChg_B7_24 65535 "Invalid" ;
VAL_ 2335633065 M2P_SysremEngy_Chg_B7_25 65535 "Invalid" ;
VAL_ 2335633065 M2P_SysremEngy_DisChg_B7_25 65535 "Invalid" ;
VAL_ 2335633066 M2P_SysremEngy_Chg_B7_26 65535 "Invalid" ;
VAL_ 2335633066 M2P_SysremEngy_DisChg_B7_26 65535 "Invalid" ;
VAL_ 2335633067 M2P_SysremEngy_Chg_B7_27 65535 "Invalid" ;
VAL_ 2335633067 M2P_SysremEngy_DisChg_B7_27 65535 "Invalid" ;
VAL_ 2335633068 M2P_SysremEngy_Chg_B7_28 65535 "Invalid" ;
VAL_ 2335633068 M2P_SysremEngy_DisChg_B7_28 65535 "Invalid" ;
VAL_ 2335633069 M2P_SysremEngy_Chg_B7_29 65535 "Invalid" ;
VAL_ 2335633069 M2P_SysremEngy_DisChg_B7_29 65535 "Invalid" ;
VAL_ 2335633070 M2P_SysremEngy_Chg_B7_30 65535 "Invalid" ;
VAL_ 2335633070 M2P_SysremEngy_DisChg_B7_30 65535 "Invalid" ;
VAL_ 2335633071 M2P_SysremEngy_Chg_B7_31 65535 "Invalid" ;
VAL_ 2335633071 M2P_SysremEngy_DisChg_B7_31 65535 "Invalid" ;
VAL_ 2335698577 M2P_BMS_Status_B7 0 "初始化状态" 1 "非满充满放状态" 2 "满充状态" 3 "满放状态" ;
VAL_ 2335698577 M2P_SOC_B7 1023 "Null" ;
VAL_ 2335698577 M2P_SOH_B7 255 "Null" ;
VAL_ 2335698578 M2P_BMS_Status_B7 0 "初始化状态" 1 "非满充满放状态" 2 "满充状态" 3 "满放状态" ;
VAL_ 2335698578 M2P_SOC_B7 1023 "Null" ;
VAL_ 2335698578 M2P_SOH_B7 255 "Null" ;
VAL_ 2335698579 M2P_BMS_Status_B7 0 "初始化状态" 1 "非满充满放状态" 2 "满充状态" 3 "满放状态" ;
VAL_ 2335698579 M2P_SOC_B7 1023 "Null" ;
VAL_ 2335698579 M2P_SOH_B7 255 "Null" ;
VAL_ 2335698580 M2P_BMS_Status_B7 0 "初始化状态" 1 "非满充满放状态" 2 "满充状态" 3 "满放状态" ;
VAL_ 2335698580 M2P_SOC_B7 1023 "Null" ;
VAL_ 2335698580 M2P_SOH_B7 255 "Null" ;
VAL_ 2335698581 M2P_BMS_Status_B7 0 "初始化状态" 1 "非满充满放状态" 2 "满充状态" 3 "满放状态" ;
VAL_ 2335698581 M2P_SOC_B7 1023 "Null" ;
VAL_ 2335698581 M2P_SOH_B7 255 "Null" ;
VAL_ 2335698582 M2P_BMS_Status_B7 0 "初始化状态" 1 "非满充满放状态" 2 "满充状态" 3 "满放状态" ;
VAL_ 2335698582 M2P_SOC_B7 1023 "Null" ;
VAL_ 2335698582 M2P_SOH_B7 255 "Null" ;
VAL_ 2335698583 M2P_BMS_Status_B7 0 "初始化状态" 1 "非满充满放状态" 2 "满充状态" 3 "满放状态" ;
VAL_ 2335698583 M2P_SOC_B7 1023 "Null" ;
VAL_ 2335698583 M2P_SOH_B7 255 "Null" ;
VAL_ 2335698584 M2P_BMS_Status_B7 0 "初始化状态" 1 "非满充满放状态" 2 "满充状态" 3 "满放状态" ;
VAL_ 2335698584 M2P_SOC_B7 1023 "Null" ;
VAL_ 2335698584 M2P_SOH_B7 255 "Null" ;
VAL_ 2335698585 M2P_BMS_Status_B7 0 "初始化状态" 1 "非满充满放状态" 2 "满充状态" 3 "满放状态" ;
VAL_ 2335698585 M2P_SOC_B7 1023 "Null" ;
VAL_ 2335698585 M2P_SOH_B7 255 "Null" ;
VAL_ 2335698586 M2P_BMS_Status_B7 0 "初始化状态" 1 "非满充满放状态" 2 "满充状态" 3 "满放状态" ;
VAL_ 2335698586 M2P_SOC_B7 1023 "Null" ;
VAL_ 2335698586 M2P_SOH_B7 255 "Null" ;
VAL_ 2335698587 M2P_BMS_Status_B7 0 "初始化状态" 1 "非满充满放状态" 2 "满充状态" 3 "满放状态" ;
VAL_ 2335698587 M2P_SOC_B7 1023 "Null" ;
VAL_ 2335698587 M2P_SOH_B7 255 "Null" ;
VAL_ 2335698588 M2P_BMS_Status_B7 0 "初始化状态" 1 "非满充满放状态" 2 "满充状态" 3 "满放状态" ;
VAL_ 2335698588 M2P_SOC_B7 1023 "Null" ;
VAL_ 2335698588 M2P_SOH_B7 255 "Null" ;
VAL_ 2335698589 M2P_BMS_Status_B7 0 "初始化状态" 1 "非满充满放状态" 2 "满充状态" 3 "满放状态" ;
VAL_ 2335698589 M2P_SOC_B7 1023 "Null" ;
VAL_ 2335698589 M2P_SOH_B7 255 "Null" ;
VAL_ 2335698590 M2P_BMS_Status_B7 0 "初始化状态" 1 "非满充满放状态" 2 "满充状态" 3 "满放状态" ;
VAL_ 2335698590 M2P_SOC_B7 1023 "Null" ;
VAL_ 2335698590 M2P_SOH_B7 255 "Null" ;
VAL_ 2335698591 M2P_BMS_Status_B7 0 "初始化状态" 1 "非满充满放状态" 2 "满充状态" 3 "满放状态" ;
VAL_ 2335698591 M2P_SOC_B7 1023 "Null" ;
VAL_ 2335698591 M2P_SOH_B7 255 "Null" ;
VAL_ 2335698592 M2P_BMS_Status_B7 0 "初始化状态" 1 "非满充满放状态" 2 "满充状态" 3 "满放状态" ;
VAL_ 2335698592 M2P_SOC_B7 1023 "Null" ;
VAL_ 2335698592 M2P_SOH_B7 255 "Null" ;
VAL_ 2335698593 M2P_BMS_Status_B7 0 "初始化状态" 1 "非满充满放状态" 2 "满充状态" 3 "满放状态" ;
VAL_ 2335698593 M2P_SOC_B7 1023 "Null" ;
VAL_ 2335698593 M2P_SOH_B7 255 "Null" ;
VAL_ 2335698594 M2P_BMS_Status_B7 0 "初始化状态" 1 "非满充满放状态" 2 "满充状态" 3 "满放状态" ;
VAL_ 2335698594 M2P_SOC_B7 1023 "Null" ;
VAL_ 2335698594 M2P_SOH_B7 255 "Null" ;
VAL_ 2335698595 M2P_BMS_Status_B7 0 "初始化状态" 1 "非满充满放状态" 2 "满充状态" 3 "满放状态" ;
VAL_ 2335698595 M2P_SOC_B7 1023 "Null" ;
VAL_ 2335698595 M2P_SOH_B7 255 "Null" ;
VAL_ 2335698596 M2P_BMS_Status_B7 0 "初始化状态" 1 "非满充满放状态" 2 "满充状态" 3 "满放状态" ;
VAL_ 2335698596 M2P_SOC_B7 1023 "Null" ;
VAL_ 2335698596 M2P_SOH_B7 255 "Null" ;
VAL_ 2335698597 M2P_BMS_Status_B7 0 "初始化状态" 1 "非满充满放状态" 2 "满充状态" 3 "满放状态" ;
VAL_ 2335698597 M2P_SOC_B7 1023 "Null" ;
VAL_ 2335698597 M2P_SOH_B7 255 "Null" ;
VAL_ 2335698598 M2P_BMS_Status_B7 0 "初始化状态" 1 "非满充满放状态" 2 "满充状态" 3 "满放状态" ;
VAL_ 2335698598 M2P_SOC_B7 1023 "Null" ;
VAL_ 2335698598 M2P_SOH_B7 255 "Null" ;
VAL_ 2335698599 M2P_BMS_Status_B7 0 "初始化状态" 1 "非满充满放状态" 2 "满充状态" 3 "满放状态" ;
VAL_ 2335698599 M2P_SOC_B7 1023 "Null" ;
VAL_ 2335698599 M2P_SOH_B7 255 "Null" ;
VAL_ 2335698600 M2P_BMS_Status_B7 0 "初始化状态" 1 "非满充满放状态" 2 "满充状态" 3 "满放状态" ;
VAL_ 2335698600 M2P_SOC_B7 1023 "Null" ;
VAL_ 2335698600 M2P_SOH_B7 255 "Null" ;
VAL_ 2335698601 M2P_BMS_Status_B7 0 "初始化状态" 1 "非满充满放状态" 2 "满充状态" 3 "满放状态" ;
VAL_ 2335698601 M2P_SOC_B7 1023 "Null" ;
VAL_ 2335698601 M2P_SOH_B7 255 "Null" ;
VAL_ 2335698602 M2P_BMS_Status_B7 0 "初始化状态" 1 "非满充满放状态" 2 "满充状态" 3 "满放状态" ;
VAL_ 2335698602 M2P_SOC_B7 1023 "Null" ;
VAL_ 2335698602 M2P_SOH_B7 255 "Null" ;
VAL_ 2335698603 M2P_BMS_Status_B7 0 "初始化状态" 1 "非满充满放状态" 2 "满充状态" 3 "满放状态" ;
VAL_ 2335698603 M2P_SOC_B7 1023 "Null" ;
VAL_ 2335698603 M2P_SOH_B7 255 "Null" ;
VAL_ 2335698604 M2P_BMS_Status_B7 0 "初始化状态" 1 "非满充满放状态" 2 "满充状态" 3 "满放状态" ;
VAL_ 2335698604 M2P_SOC_B7 1023 "Null" ;
VAL_ 2335698604 M2P_SOH_B7 255 "Null" ;
VAL_ 2335698605 M2P_BMS_Status_B7 0 "初始化状态" 1 "非满充满放状态" 2 "满充状态" 3 "满放状态" ;
VAL_ 2335698605 M2P_SOC_B7 1023 "Null" ;
VAL_ 2335698605 M2P_SOH_B7 255 "Null" ;
VAL_ 2335698606 M2P_BMS_Status_B7 0 "初始化状态" 1 "非满充满放状态" 2 "满充状态" 3 "满放状态" ;
VAL_ 2335698606 M2P_SOC_B7 1023 "Null" ;
VAL_ 2335698606 M2P_SOH_B7 255 "Null" ;
VAL_ 2335698607 M2P_BMS_Status_B7 0 "初始化状态" 1 "非满充满放状态" 2 "满充状态" 3 "满放状态" ;
VAL_ 2335698607 M2P_SOC_B7 1023 "Null" ;
VAL_ 2335698607 M2P_SOH_B7 255 "Null" ;
VAL_ 2335764113 M2P_SOE_Charge_B7 1023 "Null" ;
VAL_ 2335764113 M2P_SOE_Discharge_B7 1023 "Null" ;
VAL_ 2335764114 M2P_SOE_Charge_B7 1023 "Null" ;
VAL_ 2335764114 M2P_SOE_Discharge_B7 1023 "Null" ;
VAL_ 2335764115 M2P_SOE_Charge_B7 1023 "Null" ;
VAL_ 2335764115 M2P_SOE_Discharge_B7 1023 "Null" ;
VAL_ 2335764116 M2P_SOE_Charge_B7 1023 "Null" ;
VAL_ 2335764116 M2P_SOE_Discharge_B7 1023 "Null" ;
VAL_ 2335764117 M2P_SOE_Charge_B7 1023 "Null" ;
VAL_ 2335764117 M2P_SOE_Discharge_B7 1023 "Null" ;
VAL_ 2335764118 M2P_SOE_Charge_B7 1023 "Null" ;
VAL_ 2335764118 M2P_SOE_Discharge_B7 1023 "Null" ;
VAL_ 2335764119 M2P_SOE_Charge_B7 1023 "Null" ;
VAL_ 2335764119 M2P_SOE_Discharge_B7 1023 "Null" ;
VAL_ 2335764120 M2P_SOE_Charge_B7 1023 "Null" ;
VAL_ 2335764120 M2P_SOE_Discharge_B7 1023 "Null" ;
VAL_ 2335764121 M2P_SOE_Charge_B7 1023 "Null" ;
VAL_ 2335764121 M2P_SOE_Discharge_B7 1023 "Null" ;
VAL_ 2335764122 M2P_SOE_Charge_B7 1023 "Null" ;
VAL_ 2335764122 M2P_SOE_Discharge_B7 1023 "Null" ;
VAL_ 2335764123 M2P_SOE_Charge_B7 1023 "Null" ;
VAL_ 2335764123 M2P_SOE_Discharge_B7 1023 "Null" ;
VAL_ 2335764124 M2P_SOE_Charge_B7 1023 "Null" ;
VAL_ 2335764124 M2P_SOE_Discharge_B7 1023 "Null" ;
VAL_ 2335764125 M2P_SOE_Charge_B7 1023 "Null" ;
VAL_ 2335764125 M2P_SOE_Discharge_B7 1023 "Null" ;
VAL_ 2335764126 M2P_SOE_Charge_B7 1023 "Null" ;
VAL_ 2335764126 M2P_SOE_Discharge_B7 1023 "Null" ;
VAL_ 2335764127 M2P_SOE_Charge_B7 1023 "Null" ;
VAL_ 2335764127 M2P_SOE_Discharge_B7 1023 "Null" ;
VAL_ 2335764128 M2P_SOE_Charge_B7 1023 "Null" ;
VAL_ 2335764128 M2P_SOE_Discharge_B7 1023 "Null" ;
VAL_ 2335764129 M2P_SOE_Charge_B7 1023 "Null" ;
VAL_ 2335764129 M2P_SOE_Discharge_B7 1023 "Null" ;
VAL_ 2335764130 M2P_SOE_Charge_B7 1023 "Null" ;
VAL_ 2335764130 M2P_SOE_Discharge_B7 1023 "Null" ;
VAL_ 2335764131 M2P_SOE_Charge_B7 1023 "Null" ;
VAL_ 2335764131 M2P_SOE_Discharge_B7 1023 "Null" ;
VAL_ 2335764132 M2P_SOE_Charge_B7 1023 "Null" ;
VAL_ 2335764132 M2P_SOE_Discharge_B7 1023 "Null" ;
VAL_ 2335764133 M2P_SOE_Charge_B7 1023 "Null" ;
VAL_ 2335764133 M2P_SOE_Discharge_B7 1023 "Null" ;
VAL_ 2335764134 M2P_SOE_Charge_B7 1023 "Null" ;
VAL_ 2335764134 M2P_SOE_Discharge_B7 1023 "Null" ;
VAL_ 2335764135 M2P_SOE_Charge_B7 1023 "Null" ;
VAL_ 2335764135 M2P_SOE_Discharge_B7 1023 "Null" ;
VAL_ 2335764136 M2P_SOE_Charge_B7 1023 "Null" ;
VAL_ 2335764136 M2P_SOE_Discharge_B7 1023 "Null" ;
VAL_ 2335764137 M2P_SOE_Charge_B7 1023 "Null" ;
VAL_ 2335764137 M2P_SOE_Discharge_B7 1023 "Null" ;
VAL_ 2335764138 M2P_SOE_Charge_B7 1023 "Null" ;
VAL_ 2335764138 M2P_SOE_Discharge_B7 1023 "Null" ;
VAL_ 2335764139 M2P_SOE_Charge_B7 1023 "Null" ;
VAL_ 2335764139 M2P_SOE_Discharge_B7 1023 "Null" ;
VAL_ 2335764140 M2P_SOE_Charge_B7 1023 "Null" ;
VAL_ 2335764140 M2P_SOE_Discharge_B7 1023 "Null" ;
VAL_ 2335764141 M2P_SOE_Charge_B7 1023 "Null" ;
VAL_ 2335764141 M2P_SOE_Discharge_B7 1023 "Null" ;
VAL_ 2335764142 M2P_SOE_Charge_B7 1023 "Null" ;
VAL_ 2335764142 M2P_SOE_Discharge_B7 1023 "Null" ;
VAL_ 2335764143 M2P_SOE_Charge_B7 1023 "Null" ;
VAL_ 2335764143 M2P_SOE_Discharge_B7 1023 "Null" ;
VAL_ 2335829649 M2P_Measure_Vol_B8_01 65535 "Invalid" ;
VAL_ 2335829649 M2P_Current_B8_01 65535 "Invalid" ;
VAL_ 2335829649 M2P_PermitMaxCharge_I_B8_01 65535 "Invalid" ;
VAL_ 2335829649 M2P_PermitMaxDisCharge_I_B8_01 65535 "Invalid" ;
VAL_ 2335829650 M2P_Measure_Vol_B8_02 65535 "Invalid" ;
VAL_ 2335829650 M2P_Current_B8_02 65535 "Invalid" ;
VAL_ 2335829650 M2P_PermitMaxCharge_I_B8_02 65535 "Invalid" ;
VAL_ 2335829650 M2P_PermitMaxDisCharge_I_B8_02 65535 "Invalid" ;
VAL_ 2335829651 M2P_Measure_Vol_B8_03 65535 "Invalid" ;
VAL_ 2335829651 M2P_Current_B8_03 65535 "Invalid" ;
VAL_ 2335829651 M2P_PermitMaxCharge_I_B8_03 65535 "Invalid" ;
VAL_ 2335829651 M2P_PermitMaxDisCharge_I_B8_03 65535 "Invalid" ;
VAL_ 2335829652 M2P_Measure_Vol_B8_04 65535 "Invalid" ;
VAL_ 2335829652 M2P_Current_B8_04 65535 "Invalid" ;
VAL_ 2335829652 M2P_PermitMaxCharge_I_B8_04 65535 "Invalid" ;
VAL_ 2335829652 M2P_PermitMaxDisCharge_I_B8_04 65535 "Invalid" ;
VAL_ 2335829653 M2P_Measure_Vol_B8_05 65535 "Invalid" ;
VAL_ 2335829653 M2P_Current_B8_05 65535 "Invalid" ;
VAL_ 2335829653 M2P_PermitMaxCharge_I_B8_05 65535 "Invalid" ;
VAL_ 2335829653 M2P_PermitMaxDisCharge_I_B8_05 65535 "Invalid" ;
VAL_ 2335829654 M2P_Measure_Vol_B8_06 65535 "Invalid" ;
VAL_ 2335829654 M2P_Current_B8_06 65535 "Invalid" ;
VAL_ 2335829654 M2P_PermitMaxCharge_I_B8_06 65535 "Invalid" ;
VAL_ 2335829654 M2P_PermitMaxDisCharge_I_B8_06 65535 "Invalid" ;
VAL_ 2335829655 M2P_Measure_Vol_B8_07 65535 "Invalid" ;
VAL_ 2335829655 M2P_Current_B8_07 65535 "Invalid" ;
VAL_ 2335829655 M2P_PermitMaxCharge_I_B8_07 65535 "Invalid" ;
VAL_ 2335829655 M2P_PermitMaxDisCharge_I_B8_07 65535 "Invalid" ;
VAL_ 2335829656 M2P_Measure_Vol_B8_08 65535 "Invalid" ;
VAL_ 2335829656 M2P_Current_B8_08 65535 "Invalid" ;
VAL_ 2335829656 M2P_PermitMaxCharge_I_B8_08 65535 "Invalid" ;
VAL_ 2335829656 M2P_PermitMaxDisCharge_I_B8_08 65535 "Invalid" ;
VAL_ 2335829657 M2P_Measure_Vol_B8_09 65535 "Invalid" ;
VAL_ 2335829657 M2P_Current_B8_09 65535 "Invalid" ;
VAL_ 2335829657 M2P_PermitMaxCharge_I_B8_09 65535 "Invalid" ;
VAL_ 2335829657 M2P_PermitMaxDisCharge_I_B8_09 65535 "Invalid" ;
VAL_ 2335829658 M2P_Measure_Vol_B8_10 65535 "Invalid" ;
VAL_ 2335829658 M2P_Current_B8_10 65535 "Invalid" ;
VAL_ 2335829658 M2P_PermitMaxCharge_I_B8_10 65535 "Invalid" ;
VAL_ 2335829658 M2P_PermitMaxDisCharge_I_B8_10 65535 "Invalid" ;
VAL_ 2335829659 M2P_Measure_Vol_B8_11 65535 "Invalid" ;
VAL_ 2335829659 M2P_Current_B8_11 65535 "Invalid" ;
VAL_ 2335829659 M2P_PermitMaxCharge_I_B8_11 65535 "Invalid" ;
VAL_ 2335829659 M2P_PermitMaxDisCharge_I_B8_11 65535 "Invalid" ;
VAL_ 2335829660 M2P_Measure_Vol_B8_12 65535 "Invalid" ;
VAL_ 2335829660 M2P_Current_B8_12 65535 "Invalid" ;
VAL_ 2335829660 M2P_PermitMaxCharge_I_B8_12 65535 "Invalid" ;
VAL_ 2335829660 M2P_PermitMaxDisCharge_I_B8_12 65535 "Invalid" ;
VAL_ 2335829661 M2P_Measure_Vol_B8_13 65535 "Invalid" ;
VAL_ 2335829661 M2P_Current_B8_13 65535 "Invalid" ;
VAL_ 2335829661 M2P_PermitMaxCharge_I_B8_13 65535 "Invalid" ;
VAL_ 2335829661 M2P_PermitMaxDisCharge_I_B8_13 65535 "Invalid" ;
VAL_ 2335829662 M2P_Measure_Vol_B8_14 65535 "Invalid" ;
VAL_ 2335829662 M2P_Current_B8_14 65535 "Invalid" ;
VAL_ 2335829662 M2P_PermitMaxCharge_I_B8_14 65535 "Invalid" ;
VAL_ 2335829662 M2P_PermitMaxDisCharge_I_B8_14 65535 "Invalid" ;
VAL_ 2335829663 M2P_Measure_Vol_B8_15 65535 "Invalid" ;
VAL_ 2335829663 M2P_Current_B8_15 65535 "Invalid" ;
VAL_ 2335829663 M2P_PermitMaxCharge_I_B8_15 65535 "Invalid" ;
VAL_ 2335829663 M2P_PermitMaxDisCharge_I_B8_15 65535 "Invalid" ;
VAL_ 2335829664 M2P_Measure_Vol_B8_16 65535 "Invalid" ;
VAL_ 2335829664 M2P_Current_B8_16 65535 "Invalid" ;
VAL_ 2335829664 M2P_PermitMaxCharge_I_B8_16 65535 "Invalid" ;
VAL_ 2335829664 M2P_PermitMaxDisCharge_I_B8_16 65535 "Invalid" ;
VAL_ 2335829665 M2P_Measure_Vol_B8_17 65535 "Invalid" ;
VAL_ 2335829665 M2P_Current_B8_17 65535 "Invalid" ;
VAL_ 2335829665 M2P_PermitMaxCharge_I_B8_17 65535 "Invalid" ;
VAL_ 2335829665 M2P_PermitMaxDisCharge_I_B8_17 65535 "Invalid" ;
VAL_ 2335829666 M2P_Measure_Vol_B8_18 65535 "Invalid" ;
VAL_ 2335829666 M2P_Current_B8_18 65535 "Invalid" ;
VAL_ 2335829666 M2P_PermitMaxCharge_I_B8_18 65535 "Invalid" ;
VAL_ 2335829666 M2P_PermitMaxDisCharge_I_B8_18 65535 "Invalid" ;
VAL_ 2335829667 M2P_Measure_Vol_B8_19 65535 "Invalid" ;
VAL_ 2335829667 M2P_Current_B8_19 65535 "Invalid" ;
VAL_ 2335829667 M2P_PermitMaxCharge_I_B8_19 65535 "Invalid" ;
VAL_ 2335829667 M2P_PermitMaxDisCharge_I_B8_19 65535 "Invalid" ;
VAL_ 2335829668 M2P_Measure_Vol_B8_20 65535 "Invalid" ;
VAL_ 2335829668 M2P_Current_B8_20 65535 "Invalid" ;
VAL_ 2335829668 M2P_PermitMaxCharge_I_B8_20 65535 "Invalid" ;
VAL_ 2335829668 M2P_PermitMaxDisCharge_I_B8_20 65535 "Invalid" ;
VAL_ 2335829669 M2P_Measure_Vol_B8_21 65535 "Invalid" ;
VAL_ 2335829669 M2P_Current_B8_21 65535 "Invalid" ;
VAL_ 2335829669 M2P_PermitMaxCharge_I_B8_21 65535 "Invalid" ;
VAL_ 2335829669 M2P_PermitMaxDisCharge_I_B8_21 65535 "Invalid" ;
VAL_ 2335829670 M2P_Measure_Vol_B8_22 65535 "Invalid" ;
VAL_ 2335829670 M2P_Current_B8_22 65535 "Invalid" ;
VAL_ 2335829670 M2P_PermitMaxCharge_I_B8_22 65535 "Invalid" ;
VAL_ 2335829670 M2P_PermitMaxDisCharge_I_B8_22 65535 "Invalid" ;
VAL_ 2335829671 M2P_Measure_Vol_B8_23 65535 "Invalid" ;
VAL_ 2335829671 M2P_Current_B8_23 65535 "Invalid" ;
VAL_ 2335829671 M2P_PermitMaxCharge_I_B8_23 65535 "Invalid" ;
VAL_ 2335829671 M2P_PermitMaxDisCharge_I_B8_23 65535 "Invalid" ;
VAL_ 2335829672 M2P_Measure_Vol_B8_24 65535 "Invalid" ;
VAL_ 2335829672 M2P_Current_B8_24 65535 "Invalid" ;
VAL_ 2335829672 M2P_PermitMaxCharge_I_B8_24 65535 "Invalid" ;
VAL_ 2335829672 M2P_PermitMaxDisCharge_I_B8_24 65535 "Invalid" ;
VAL_ 2335829673 M2P_Measure_Vol_B8_25 65535 "Invalid" ;
VAL_ 2335829673 M2P_Current_B8_25 65535 "Invalid" ;
VAL_ 2335829673 M2P_PermitMaxCharge_I_B8_25 65535 "Invalid" ;
VAL_ 2335829673 M2P_PermitMaxDisCharge_I_B8_25 65535 "Invalid" ;
VAL_ 2335829674 M2P_Measure_Vol_B8_26 65535 "Invalid" ;
VAL_ 2335829674 M2P_Current_B8_26 65535 "Invalid" ;
VAL_ 2335829674 M2P_PermitMaxCharge_I_B8_26 65535 "Invalid" ;
VAL_ 2335829674 M2P_PermitMaxDisCharge_I_B8_26 65535 "Invalid" ;
VAL_ 2335829675 M2P_Measure_Vol_B8_27 65535 "Invalid" ;
VAL_ 2335829675 M2P_Current_B8_27 65535 "Invalid" ;
VAL_ 2335829675 M2P_PermitMaxCharge_I_B8_27 65535 "Invalid" ;
VAL_ 2335829675 M2P_PermitMaxDisCharge_I_B8_27 65535 "Invalid" ;
VAL_ 2335829676 M2P_Measure_Vol_B8_28 65535 "Invalid" ;
VAL_ 2335829676 M2P_Current_B8_28 65535 "Invalid" ;
VAL_ 2335829676 M2P_PermitMaxCharge_I_B8_28 65535 "Invalid" ;
VAL_ 2335829676 M2P_PermitMaxDisCharge_I_B8_28 65535 "Invalid" ;
VAL_ 2335829677 M2P_Measure_Vol_B8_29 65535 "Invalid" ;
VAL_ 2335829677 M2P_Current_B8_29 65535 "Invalid" ;
VAL_ 2335829677 M2P_PermitMaxCharge_I_B8_29 65535 "Invalid" ;
VAL_ 2335829677 M2P_PermitMaxDisCharge_I_B8_29 65535 "Invalid" ;
VAL_ 2335829678 M2P_Measure_Vol_B8_30 65535 "Invalid" ;
VAL_ 2335829678 M2P_Current_B8_30 65535 "Invalid" ;
VAL_ 2335829678 M2P_PermitMaxCharge_I_B8_30 65535 "Invalid" ;
VAL_ 2335829678 M2P_PermitMaxDisCharge_I_B8_30 65535 "Invalid" ;
VAL_ 2335829679 M2P_Measure_Vol_B8_31 65535 "Invalid" ;
VAL_ 2335829679 M2P_Current_B8_31 65535 "Invalid" ;
VAL_ 2335829679 M2P_PermitMaxCharge_I_B8_31 65535 "Invalid" ;
VAL_ 2335829679 M2P_PermitMaxDisCharge_I_B8_31 65535 "Invalid" ;
VERSION ""

NS_ :

BS_:

BU_: MBMU PC SBMU IMM ETH DCDC LEMS

BO_ 2335895201 M2P_SUMDATA51__17: 8 MBMU
 SG_ M2P_PermitMaxVolt_B8_17 : 0|16@1+ (0.1,0) [0|6553.5] "V"  PC
 SG_ M2P_PermitMinVolt_B8_17 : 16|16@1+ (0.1,0) [0|6553.5] "V"  PC
 SG_ M2P_PermitMaxPow_Chg_B8_17 : 32|16@1+ (1,-20000) [-20000|45535] "Kw"  PC
 SG_ M2P_PermitMaxPow_DisChg_B8_17 : 48|16@1+ (1,-20000) [-20000|45535] "Kw"  PC

BO_ 2335895202 M2P_SUMDATA51__18: 8 MBMU
 SG_ M2P_PermitMaxVolt_B8_18 : 0|16@1+ (0.1,0) [0|6553.5] "V"  PC
 SG_ M2P_PermitMinVolt_B8_18 : 16|16@1+ (0.1,0) [0|6553.5] "V"  PC
 SG_ M2P_PermitMaxPow_Chg_B8_18 : 32|16@1+ (1,-20000) [-20000|45535] "Kw"  PC
 SG_ M2P_PermitMaxPow_DisChg_B8_18 : 48|16@1+ (1,-20000) [-20000|45535] "Kw"  PC

BO_ 2335895203 M2P_SUMDATA51__19: 8 MBMU
 SG_ M2P_PermitMaxVolt_B8_19 : 0|16@1+ (0.1,0) [0|6553.5] "V"  PC
 SG_ M2P_PermitMinVolt_B8_19 : 16|16@1+ (0.1,0) [0|6553.5] "V"  PC
 SG_ M2P_PermitMaxPow_Chg_B8_19 : 32|16@1+ (1,-20000) [-20000|45535] "Kw"  PC
 SG_ M2P_PermitMaxPow_DisChg_B8_19 : 48|16@1+ (1,-20000) [-20000|45535] "Kw"  PC

BO_ 2335895204 M2P_SUMDATA51__20: 8 MBMU
 SG_ M2P_PermitMaxVolt_B8_20 : 0|16@1+ (0.1,0) [0|6553.5] "V"  PC
 SG_ M2P_PermitMinVolt_B8_20 : 16|16@1+ (0.1,0) [0|6553.5] "V"  PC
 SG_ M2P_PermitMaxPow_Chg_B8_20 : 32|16@1+ (1,-20000) [-20000|45535] "Kw"  PC
 SG_ M2P_PermitMaxPow_DisChg_B8_20 : 48|16@1+ (1,-20000) [-20000|45535] "Kw"  PC

BO_ 2335895205 M2P_SUMDATA51__21: 8 MBMU
 SG_ M2P_PermitMaxVolt_B8_21 : 0|16@1+ (0.1,0) [0|6553.5] "V"  PC
 SG_ M2P_PermitMinVolt_B8_21 : 16|16@1+ (0.1,0) [0|6553.5] "V"  PC
 SG_ M2P_PermitMaxPow_Chg_B8_21 : 32|16@1+ (1,-20000) [-20000|45535] "Kw"  PC
 SG_ M2P_PermitMaxPow_DisChg_B8_21 : 48|16@1+ (1,-20000) [-20000|45535] "Kw"  PC

BO_ 2335895206 M2P_SUMDATA51__22: 8 MBMU
 SG_ M2P_PermitMaxVolt_B8_22 : 0|16@1+ (0.1,0) [0|6553.5] "V"  PC
 SG_ M2P_PermitMinVolt_B8_22 : 16|16@1+ (0.1,0) [0|6553.5] "V"  PC
 SG_ M2P_PermitMaxPow_Chg_B8_22 : 32|16@1+ (1,-20000) [-20000|45535] "Kw"  PC
 SG_ M2P_PermitMaxPow_DisChg_B8_22 : 48|16@1+ (1,-20000) [-20000|45535] "Kw"  PC

BO_ 2335895207 M2P_SUMDATA51__23: 8 MBMU
 SG_ M2P_PermitMaxVolt_B8_23 : 0|16@1+ (0.1,0) [0|6553.5] "V"  PC
 SG_ M2P_PermitMinVolt_B8_23 : 16|16@1+ (0.1,0) [0|6553.5] "V"  PC
 SG_ M2P_PermitMaxPow_Chg_B8_23 : 32|16@1+ (1,-20000) [-20000|45535] "Kw"  PC
 SG_ M2P_PermitMaxPow_DisChg_B8_23 : 48|16@1+ (1,-20000) [-20000|45535] "Kw"  PC

BO_ 2335895208 M2P_SUMDATA51__24: 8 MBMU
 SG_ M2P_PermitMaxVolt_B8_24 : 0|16@1+ (0.1,0) [0|6553.5] "V"  PC
 SG_ M2P_PermitMinVolt_B8_24 : 16|16@1+ (0.1,0) [0|6553.5] "V"  PC
 SG_ M2P_PermitMaxPow_Chg_B8_24 : 32|16@1+ (1,-20000) [-20000|45535] "Kw"  PC
 SG_ M2P_PermitMaxPow_DisChg_B8_24 : 48|16@1+ (1,-20000) [-20000|45535] "Kw"  PC

BO_ 2335895209 M2P_SUMDATA51__25: 8 MBMU
 SG_ M2P_PermitMaxVolt_B8_25 : 0|16@1+ (0.1,0) [0|6553.5] "V"  PC
 SG_ M2P_PermitMinVolt_B8_25 : 16|16@1+ (0.1,0) [0|6553.5] "V"  PC
 SG_ M2P_PermitMaxPow_Chg_B8_25 : 32|16@1+ (1,-20000) [-20000|45535] "Kw"  PC
 SG_ M2P_PermitMaxPow_DisChg_B8_25 : 48|16@1+ (1,-20000) [-20000|45535] "Kw"  PC

BO_ 2335895210 M2P_SUMDATA51__26: 8 MBMU
 SG_ M2P_PermitMaxVolt_B8_26 : 0|16@1+ (0.1,0) [0|6553.5] "V"  PC
 SG_ M2P_PermitMinVolt_B8_26 : 16|16@1+ (0.1,0) [0|6553.5] "V"  PC
 SG_ M2P_PermitMaxPow_Chg_B8_26 : 32|16@1+ (1,-20000) [-20000|45535] "Kw"  PC
 SG_ M2P_PermitMaxPow_DisChg_B8_26 : 48|16@1+ (1,-20000) [-20000|45535] "Kw"  PC

BO_ 2335895211 M2P_SUMDATA51__27: 8 MBMU
 SG_ M2P_PermitMaxVolt_B8_27 : 0|16@1+ (0.1,0) [0|6553.5] "V"  PC
 SG_ M2P_PermitMinVolt_B8_27 : 16|16@1+ (0.1,0) [0|6553.5] "V"  PC
 SG_ M2P_PermitMaxPow_Chg_B8_27 : 32|16@1+ (1,-20000) [-20000|45535] "Kw"  PC
 SG_ M2P_PermitMaxPow_DisChg_B8_27 : 48|16@1+ (1,-20000) [-20000|45535] "Kw"  PC

BO_ 2335895212 M2P_SUMDATA51__28: 8 MBMU
 SG_ M2P_PermitMaxVolt_B8_28 : 0|16@1+ (0.1,0) [0|6553.5] "V"  PC
 SG_ M2P_PermitMinVolt_B8_28 : 16|16@1+ (0.1,0) [0|6553.5] "V"  PC
 SG_ M2P_PermitMaxPow_Chg_B8_28 : 32|16@1+ (1,-20000) [-20000|45535] "Kw"  PC
 SG_ M2P_PermitMaxPow_DisChg_B8_28 : 48|16@1+ (1,-20000) [-20000|45535] "Kw"  PC

BO_ 2335895213 M2P_SUMDATA51__29: 8 MBMU
 SG_ M2P_PermitMaxVolt_B8_29 : 0|16@1+ (0.1,0) [0|6553.5] "V"  PC
 SG_ M2P_PermitMinVolt_B8_29 : 16|16@1+ (0.1,0) [0|6553.5] "V"  PC
 SG_ M2P_PermitMaxPow_Chg_B8_29 : 32|16@1+ (1,-20000) [-20000|45535] "Kw"  PC
 SG_ M2P_PermitMaxPow_DisChg_B8_29 : 48|16@1+ (1,-20000) [-20000|45535] "Kw"  PC

BO_ 2335895214 M2P_SUMDATA51__30: 8 MBMU
 SG_ M2P_PermitMaxVolt_B8_30 : 0|16@1+ (0.1,0) [0|6553.5] "V"  PC
 SG_ M2P_PermitMinVolt_B8_30 : 16|16@1+ (0.1,0) [0|6553.5] "V"  PC
 SG_ M2P_PermitMaxPow_Chg_B8_30 : 32|16@1+ (1,-20000) [-20000|45535] "Kw"  PC
 SG_ M2P_PermitMaxPow_DisChg_B8_30 : 48|16@1+ (1,-20000) [-20000|45535] "Kw"  PC

BO_ 2335895215 M2P_SUMDATA51__31: 8 MBMU
 SG_ M2P_PermitMaxVolt_B8_31 : 0|16@1+ (0.1,0) [0|6553.5] "V"  PC
 SG_ M2P_PermitMinVolt_B8_31 : 16|16@1+ (0.1,0) [0|6553.5] "V"  PC
 SG_ M2P_PermitMaxPow_Chg_B8_31 : 32|16@1+ (1,-20000) [-20000|45535] "Kw"  PC
 SG_ M2P_PermitMaxPow_DisChg_B8_31 : 48|16@1+ (1,-20000) [-20000|45535] "Kw"  PC

BO_ 2335960721 M2P_SUMDATA52__01: 8 MBMU
 SG_ M2P_Power_B8_01 : 0|16@1+ (1,-20000) [-20000|45535] "Kw"  PC
 SG_ M2P_SysremEngy_Chg_B8_01 : 16|16@1+ (1,0) [0|65535] "Kwh"  PC
 SG_ M2P_SysremEngy_DisChg_B8_01 : 32|16@1+ (1,0) [0|65535] "Kwh"  PC
 SG_ M2P_SysMaxVolt_B8_01 : 48|16@1+ (1,0) [0|65535] "mv"  PC

BO_ 2335960722 M2P_SUMDATA52__02: 8 MBMU
 SG_ M2P_Power_B8_02 : 0|16@1+ (1,-20000) [-20000|45535] "Kw"  PC
 SG_ M2P_SysremEngy_Chg_B8_02 : 16|16@1+ (1,0) [0|65535] "Kwh"  PC
 SG_ M2P_SysremEngy_DisChg_B8_02 : 32|16@1+ (1,0) [0|65535] "Kwh"  PC
 SG_ M2P_SysMaxVolt_B8_02 : 48|16@1+ (1,0) [0|65535] "mv"  PC

BO_ 2335960723 M2P_SUMDATA52__03: 8 MBMU
 SG_ M2P_Power_B8_03 : 0|16@1+ (1,-20000) [-20000|45535] "Kw"  PC
 SG_ M2P_SysremEngy_Chg_B8_03 : 16|16@1+ (1,0) [0|65535] "Kwh"  PC
 SG_ M2P_SysremEngy_DisChg_B8_03 : 32|16@1+ (1,0) [0|65535] "Kwh"  PC
 SG_ M2P_SysMaxVolt_B8_03 : 48|16@1+ (1,0) [0|65535] "mv"  PC

BO_ 2335960724 M2P_SUMDATA52__04: 8 MBMU
 SG_ M2P_Power_B8_04 : 0|16@1+ (1,-20000) [-20000|45535] "Kw"  PC
 SG_ M2P_SysremEngy_Chg_B8_04 : 16|16@1+ (1,0) [0|65535] "Kwh"  PC
 SG_ M2P_SysremEngy_DisChg_B8_04 : 32|16@1+ (1,0) [0|65535] "Kwh"  PC
 SG_ M2P_SysMaxVolt_B8_04 : 48|16@1+ (1,0) [0|65535] "mv"  PC

BO_ 2335960725 M2P_SUMDATA52__05: 8 MBMU
 SG_ M2P_Power_B8_05 : 0|16@1+ (1,-20000) [-20000|45535] "Kw"  PC
 SG_ M2P_SysremEngy_Chg_B8_05 : 16|16@1+ (1,0) [0|65535] "Kwh"  PC
 SG_ M2P_SysremEngy_DisChg_B8_05 : 32|16@1+ (1,0) [0|65535] "Kwh"  PC
 SG_ M2P_SysMaxVolt_B8_05 : 48|16@1+ (1,0) [0|65535] "mv"  PC

BO_ 2335960726 M2P_SUMDATA52__06: 8 MBMU
 SG_ M2P_Power_B8_06 : 0|16@1+ (1,-20000) [-20000|45535] "Kw"  PC
 SG_ M2P_SysremEngy_Chg_B8_06 : 16|16@1+ (1,0) [0|65535] "Kwh"  PC
 SG_ M2P_SysremEngy_DisChg_B8_06 : 32|16@1+ (1,0) [0|65535] "Kwh"  PC
 SG_ M2P_SysMaxVolt_B8_06 : 48|16@1+ (1,0) [0|65535] "mv"  PC

BO_ 2335960727 M2P_SUMDATA52__07: 8 MBMU
 SG_ M2P_Power_B8_07 : 0|16@1+ (1,-20000) [-20000|45535] "Kw"  PC
 SG_ M2P_SysremEngy_Chg_B8_07 : 16|16@1+ (1,0) [0|65535] "Kwh"  PC
 SG_ M2P_SysremEngy_DisChg_B8_07 : 32|16@1+ (1,0) [0|65535] "Kwh"  PC
 SG_ M2P_SysMaxVolt_B8_07 : 48|16@1+ (1,0) [0|65535] "mv"  PC

BO_ 2335960728 M2P_SUMDATA52__08: 8 MBMU
 SG_ M2P_Power_B8_08 : 0|16@1+ (1,-20000) [-20000|45535] "Kw"  PC
 SG_ M2P_SysremEngy_Chg_B8_08 : 16|16@1+ (1,0) [0|65535] "Kwh"  PC
 SG_ M2P_SysremEngy_DisChg_B8_08 : 32|16@1+ (1,0) [0|65535] "Kwh"  PC
 SG_ M2P_SysMaxVolt_B8_08 : 48|16@1+ (1,0) [0|65535] "mv"  PC

BO_ 2335960729 M2P_SUMDATA52__09: 8 MBMU
 SG_ M2P_Power_B8_09 : 0|16@1+ (1,-20000) [-20000|45535] "Kw"  PC
 SG_ M2P_SysremEngy_Chg_B8_09 : 16|16@1+ (1,0) [0|65535] "Kwh"  PC
 SG_ M2P_SysremEngy_DisChg_B8_09 : 32|16@1+ (1,0) [0|65535] "Kwh"  PC
 SG_ M2P_SysMaxVolt_B8_09 : 48|16@1+ (1,0) [0|65535] "mv"  PC

BO_ 2335960730 M2P_SUMDATA52__10: 8 MBMU
 SG_ M2P_Power_B8_10 : 0|16@1+ (1,-20000) [-20000|45535] "Kw"  PC
 SG_ M2P_SysremEngy_Chg_B8_10 : 16|16@1+ (1,0) [0|65535] "Kwh"  PC
 SG_ M2P_SysremEngy_DisChg_B8_10 : 32|16@1+ (1,0) [0|65535] "Kwh"  PC
 SG_ M2P_SysMaxVolt_B8_10 : 48|16@1+ (1,0) [0|65535] "mv"  PC

BO_ 2335960731 M2P_SUMDATA52__11: 8 MBMU
 SG_ M2P_Power_B8_11 : 0|16@1+ (1,-20000) [-20000|45535] "Kw"  PC
 SG_ M2P_SysremEngy_Chg_B8_11 : 16|16@1+ (1,0) [0|65535] "Kwh"  PC
 SG_ M2P_SysremEngy_DisChg_B8_11 : 32|16@1+ (1,0) [0|65535] "Kwh"  PC
 SG_ M2P_SysMaxVolt_B8_11 : 48|16@1+ (1,0) [0|65535] "mv"  PC

BO_ 2335960732 M2P_SUMDATA52__12: 8 MBMU
 SG_ M2P_Power_B8_12 : 0|16@1+ (1,-20000) [-20000|45535] "Kw"  PC
 SG_ M2P_SysremEngy_Chg_B8_12 : 16|16@1+ (1,0) [0|65535] "Kwh"  PC
 SG_ M2P_SysremEngy_DisChg_B8_12 : 32|16@1+ (1,0) [0|65535] "Kwh"  PC
 SG_ M2P_SysMaxVolt_B8_12 : 48|16@1+ (1,0) [0|65535] "mv"  PC

BO_ 2335960733 M2P_SUMDATA52__13: 8 MBMU
 SG_ M2P_Power_B8_13 : 0|16@1+ (1,-20000) [-20000|45535] "Kw"  PC
 SG_ M2P_SysremEngy_Chg_B8_13 : 16|16@1+ (1,0) [0|65535] "Kwh"  PC
 SG_ M2P_SysremEngy_DisChg_B8_13 : 32|16@1+ (1,0) [0|65535] "Kwh"  PC
 SG_ M2P_SysMaxVolt_B8_13 : 48|16@1+ (1,0) [0|65535] "mv"  PC

BO_ 2335960734 M2P_SUMDATA52__14: 8 MBMU
 SG_ M2P_Power_B8_14 : 0|16@1+ (1,-20000) [-20000|45535] "Kw"  PC
 SG_ M2P_SysremEngy_Chg_B8_14 : 16|16@1+ (1,0) [0|65535] "Kwh"  PC
 SG_ M2P_SysremEngy_DisChg_B8_14 : 32|16@1+ (1,0) [0|65535] "Kwh"  PC
 SG_ M2P_SysMaxVolt_B8_14 : 48|16@1+ (1,0) [0|65535] "mv"  PC

BO_ 2335960735 M2P_SUMDATA52__15: 8 MBMU
 SG_ M2P_Power_B8_15 : 0|16@1+ (1,-20000) [-20000|45535] "Kw"  PC
 SG_ M2P_SysremEngy_Chg_B8_15 : 16|16@1+ (1,0) [0|65535] "Kwh"  PC
 SG_ M2P_SysremEngy_DisChg_B8_15 : 32|16@1+ (1,0) [0|65535] "Kwh"  PC
 SG_ M2P_SysMaxVolt_B8_15 : 48|16@1+ (1,0) [0|65535] "mv"  PC

BO_ 2335960736 M2P_SUMDATA52__16: 8 MBMU
 SG_ M2P_Power_B8_16 : 0|16@1+ (1,-20000) [-20000|45535] "Kw"  PC
 SG_ M2P_SysremEngy_Chg_B8_16 : 16|16@1+ (1,0) [0|65535] "Kwh"  PC
 SG_ M2P_SysremEngy_DisChg_B8_16 : 32|16@1+ (1,0) [0|65535] "Kwh"  PC
 SG_ M2P_SysMaxVolt_B8_16 : 48|16@1+ (1,0) [0|65535] "mv"  PC

BO_ 2335960737 M2P_SUMDATA52__17: 8 MBMU
 SG_ M2P_Power_B8_17 : 0|16@1+ (1,-20000) [-20000|45535] "Kw"  PC
 SG_ M2P_SysremEngy_Chg_B8_17 : 16|16@1+ (1,0) [0|65535] "Kwh"  PC
 SG_ M2P_SysremEngy_DisChg_B8_17 : 32|16@1+ (1,0) [0|65535] "Kwh"  PC
 SG_ M2P_SysMaxVolt_B8_17 : 48|16@1+ (1,0) [0|65535] "mv"  PC

BO_ 2335960738 M2P_SUMDATA52__18: 8 MBMU
 SG_ M2P_Power_B8_18 : 0|16@1+ (1,-20000) [-20000|45535] "Kw"  PC
 SG_ M2P_SysremEngy_Chg_B8_18 : 16|16@1+ (1,0) [0|65535] "Kwh"  PC
 SG_ M2P_SysremEngy_DisChg_B8_18 : 32|16@1+ (1,0) [0|65535] "Kwh"  PC
 SG_ M2P_SysMaxVolt_B8_18 : 48|16@1+ (1,0) [0|65535] "mv"  PC

BO_ 2335960739 M2P_SUMDATA52__19: 8 MBMU
 SG_ M2P_Power_B8_19 : 0|16@1+ (1,-20000) [-20000|45535] "Kw"  PC
 SG_ M2P_SysremEngy_Chg_B8_19 : 16|16@1+ (1,0) [0|65535] "Kwh"  PC
 SG_ M2P_SysremEngy_DisChg_B8_19 : 32|16@1+ (1,0) [0|65535] "Kwh"  PC
 SG_ M2P_SysMaxVolt_B8_19 : 48|16@1+ (1,0) [0|65535] "mv"  PC

BO_ 2335960740 M2P_SUMDATA52__20: 8 MBMU
 SG_ M2P_Power_B8_20 : 0|16@1+ (1,-20000) [-20000|45535] "Kw"  PC
 SG_ M2P_SysremEngy_Chg_B8_20 : 16|16@1+ (1,0) [0|65535] "Kwh"  PC
 SG_ M2P_SysremEngy_DisChg_B8_20 : 32|16@1+ (1,0) [0|65535] "Kwh"  PC
 SG_ M2P_SysMaxVolt_B8_20 : 48|16@1+ (1,0) [0|65535] "mv"  PC

BO_ 2335960741 M2P_SUMDATA52__21: 8 MBMU
 SG_ M2P_Power_B8_21 : 0|16@1+ (1,-20000) [-20000|45535] "Kw"  PC
 SG_ M2P_SysremEngy_Chg_B8_21 : 16|16@1+ (1,0) [0|65535] "Kwh"  PC
 SG_ M2P_SysremEngy_DisChg_B8_21 : 32|16@1+ (1,0) [0|65535] "Kwh"  PC
 SG_ M2P_SysMaxVolt_B8_21 : 48|16@1+ (1,0) [0|65535] "mv"  PC

BO_ 2335960742 M2P_SUMDATA52__22: 8 MBMU
 SG_ M2P_Power_B8_22 : 0|16@1+ (1,-20000) [-20000|45535] "Kw"  PC
 SG_ M2P_SysremEngy_Chg_B8_22 : 16|16@1+ (1,0) [0|65535] "Kwh"  PC
 SG_ M2P_SysremEngy_DisChg_B8_22 : 32|16@1+ (1,0) [0|65535] "Kwh"  PC
 SG_ M2P_SysMaxVolt_B8_22 : 48|16@1+ (1,0) [0|65535] "mv"  PC

BO_ 2335960743 M2P_SUMDATA52__23: 8 MBMU
 SG_ M2P_Power_B8_23 : 0|16@1+ (1,-20000) [-20000|45535] "Kw"  PC
 SG_ M2P_SysremEngy_Chg_B8_23 : 16|16@1+ (1,0) [0|65535] "Kwh"  PC
 SG_ M2P_SysremEngy_DisChg_B8_23 : 32|16@1+ (1,0) [0|65535] "Kwh"  PC
 SG_ M2P_SysMaxVolt_B8_23 : 48|16@1+ (1,0) [0|65535] "mv"  PC

BO_ 2335960744 M2P_SUMDATA52__24: 8 MBMU
 SG_ M2P_Power_B8_24 : 0|16@1+ (1,-20000) [-20000|45535] "Kw"  PC
 SG_ M2P_SysremEngy_Chg_B8_24 : 16|16@1+ (1,0) [0|65535] "Kwh"  PC
 SG_ M2P_SysremEngy_DisChg_B8_24 : 32|16@1+ (1,0) [0|65535] "Kwh"  PC
 SG_ M2P_SysMaxVolt_B8_24 : 48|16@1+ (1,0) [0|65535] "mv"  PC

BO_ 2335960745 M2P_SUMDATA52__25: 8 MBMU
 SG_ M2P_Power_B8_25 : 0|16@1+ (1,-20000) [-20000|45535] "Kw"  PC
 SG_ M2P_SysremEngy_Chg_B8_25 : 16|16@1+ (1,0) [0|65535] "Kwh"  PC
 SG_ M2P_SysremEngy_DisChg_B8_25 : 32|16@1+ (1,0) [0|65535] "Kwh"  PC
 SG_ M2P_SysMaxVolt_B8_25 : 48|16@1+ (1,0) [0|65535] "mv"  PC

BO_ 2335960746 M2P_SUMDATA52__26: 8 MBMU
 SG_ M2P_Power_B8_26 : 0|16@1+ (1,-20000) [-20000|45535] "Kw"  PC
 SG_ M2P_SysremEngy_Chg_B8_26 : 16|16@1+ (1,0) [0|65535] "Kwh"  PC
 SG_ M2P_SysremEngy_DisChg_B8_26 : 32|16@1+ (1,0) [0|65535] "Kwh"  PC
 SG_ M2P_SysMaxVolt_B8_26 : 48|16@1+ (1,0) [0|65535] "mv"  PC

BO_ 2335960747 M2P_SUMDATA52__27: 8 MBMU
 SG_ M2P_Power_B8_27 : 0|16@1+ (1,-20000) [-20000|45535] "Kw"  PC
 SG_ M2P_SysremEngy_Chg_B8_27 : 16|16@1+ (1,0) [0|65535] "Kwh"  PC
 SG_ M2P_SysremEngy_DisChg_B8_27 : 32|16@1+ (1,0) [0|65535] "Kwh"  PC
 SG_ M2P_SysMaxVolt_B8_27 : 48|16@1+ (1,0) [0|65535] "mv"  PC

BO_ 2335960748 M2P_SUMDATA52__28: 8 MBMU
 SG_ M2P_Power_B8_28 : 0|16@1+ (1,-20000) [-20000|45535] "Kw"  PC
 SG_ M2P_SysremEngy_Chg_B8_28 : 16|16@1+ (1,0) [0|65535] "Kwh"  PC
 SG_ M2P_SysremEngy_DisChg_B8_28 : 32|16@1+ (1,0) [0|65535] "Kwh"  PC
 SG_ M2P_SysMaxVolt_B8_28 : 48|16@1+ (1,0) [0|65535] "mv"  PC

BO_ 2335960749 M2P_SUMDATA52__29: 8 MBMU
 SG_ M2P_Power_B8_29 : 0|16@1+ (1,-20000) [-20000|45535] "Kw"  PC
 SG_ M2P_SysremEngy_Chg_B8_29 : 16|16@1+ (1,0) [0|65535] "Kwh"  PC
 SG_ M2P_SysremEngy_DisChg_B8_29 : 32|16@1+ (1,0) [0|65535] "Kwh"  PC
 SG_ M2P_SysMaxVolt_B8_29 : 48|16@1+ (1,0) [0|65535] "mv"  PC

BO_ 2335960750 M2P_SUMDATA52__30: 8 MBMU
 SG_ M2P_Power_B8_30 : 0|16@1+ (1,-20000) [-20000|45535] "Kw"  PC
 SG_ M2P_SysremEngy_Chg_B8_30 : 16|16@1+ (1,0) [0|65535] "Kwh"  PC
 SG_ M2P_SysremEngy_DisChg_B8_30 : 32|16@1+ (1,0) [0|65535] "Kwh"  PC
 SG_ M2P_SysMaxVolt_B8_30 : 48|16@1+ (1,0) [0|65535] "mv"  PC

BO_ 2335960751 M2P_SUMDATA52__31: 8 MBMU
 SG_ M2P_Power_B8_31 : 0|16@1+ (1,-20000) [-20000|45535] "Kw"  PC
 SG_ M2P_SysremEngy_Chg_B8_31 : 16|16@1+ (1,0) [0|65535] "Kwh"  PC
 SG_ M2P_SysremEngy_DisChg_B8_31 : 32|16@1+ (1,0) [0|65535] "Kwh"  PC
 SG_ M2P_SysMaxVolt_B8_31 : 48|16@1+ (1,0) [0|65535] "mv"  PC

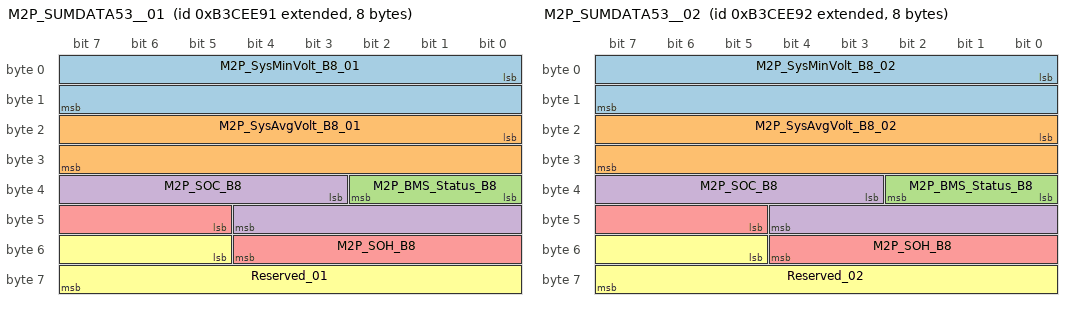
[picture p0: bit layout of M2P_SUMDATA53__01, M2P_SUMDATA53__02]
BO_ 2336026257 M2P_SUMDATA53__01: 8 MBMU
 SG_ M2P_SysMinVolt_B8_01 : 0|16@1+ (1,0) [0|65535] "mv"  PC
 SG_ M2P_SysAvgVolt_B8_01 : 16|16@1+ (1,0) [0|65535] "mv"  PC
 SG_ M2P_BMS_Status_B8 : 32|3@1+ (1,0) [0|7] ""  PC
 SG_ M2P_SOC_B8 : 35|10@1+ (0.1,0) [0|102.3] "%"  PC
 SG_ M2P_SOH_B8 : 45|8@1+ (1,0) [0|255] "%"  PC
 SG_ Reserved_01 : 53|11@1+ (1,0) [0|2047] ""  PC

BO_ 2336026258 M2P_SUMDATA53__02: 8 MBMU
 SG_ M2P_SysMinVolt_B8_02 : 0|16@1+ (1,0) [0|65535] "mv"  PC
 SG_ M2P_SysAvgVolt_B8_02 : 16|16@1+ (1,0) [0|65535] "mv"  PC
 SG_ M2P_BMS_Status_B8 : 32|3@1+ (1,0) [0|7] ""  PC
 SG_ M2P_SOC_B8 : 35|10@1+ (0.1,0) [0|102.3] "%"  PC
 SG_ M2P_SOH_B8 : 45|8@1+ (1,0) [0|255] "%"  PC
 SG_ Reserved_02 : 53|11@1+ (1,0) [0|2047] ""  PC

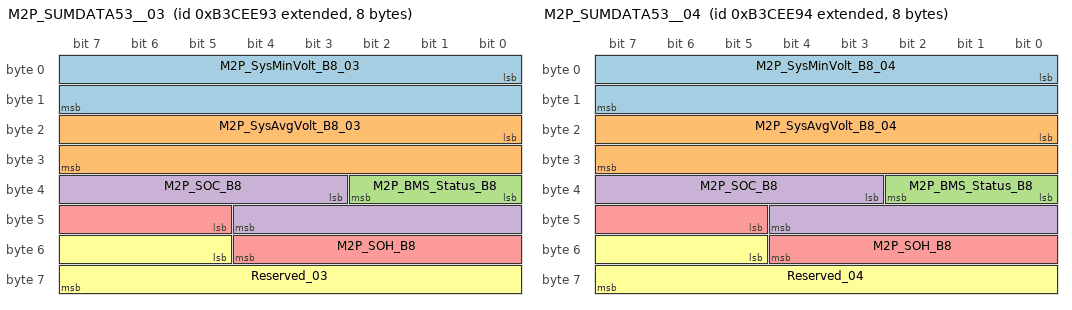
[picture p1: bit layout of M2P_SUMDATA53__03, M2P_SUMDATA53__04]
BO_ 2336026259 M2P_SUMDATA53__03: 8 MBMU
 SG_ M2P_SysMinVolt_B8_03 : 0|16@1+ (1,0) [0|65535] "mv"  PC
 SG_ M2P_SysAvgVolt_B8_03 : 16|16@1+ (1,0) [0|65535] "mv"  PC
 SG_ M2P_BMS_Status_B8 : 32|3@1+ (1,0) [0|7] ""  PC
 SG_ M2P_SOC_B8 : 35|10@1+ (0.1,0) [0|102.3] "%"  PC
 SG_ M2P_SOH_B8 : 45|8@1+ (1,0) [0|255] "%"  PC
 SG_ Reserved_03 : 53|11@1+ (1,0) [0|2047] ""  PC

BO_ 2336026260 M2P_SUMDATA53__04: 8 MBMU
 SG_ M2P_SysMinVolt_B8_04 : 0|16@1+ (1,0) [0|65535] "mv"  PC
 SG_ M2P_SysAvgVolt_B8_04 : 16|16@1+ (1,0) [0|65535] "mv"  PC
 SG_ M2P_BMS_Status_B8 : 32|3@1+ (1,0) [0|7] ""  PC
 SG_ M2P_SOC_B8 : 35|10@1+ (0.1,0) [0|102.3] "%"  PC
 SG_ M2P_SOH_B8 : 45|8@1+ (1,0) [0|255] "%"  PC
 SG_ Reserved_04 : 53|11@1+ (1,0) [0|2047] ""  PC

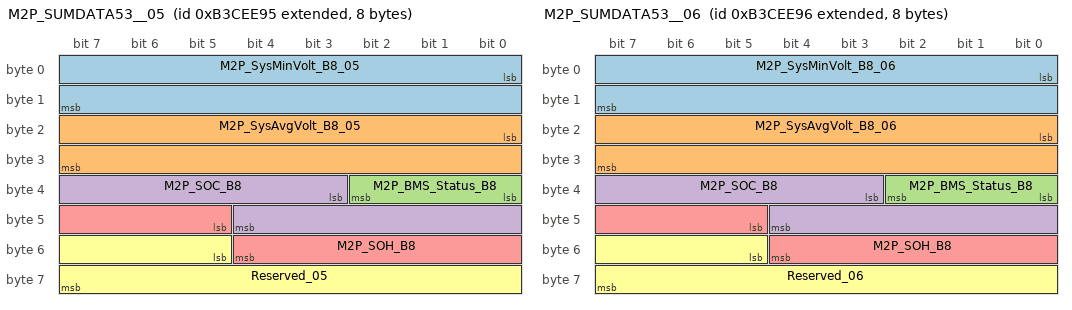
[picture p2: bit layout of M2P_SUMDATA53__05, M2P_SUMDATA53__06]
BO_ 2336026261 M2P_SUMDATA53__05: 8 MBMU
 SG_ M2P_SysMinVolt_B8_05 : 0|16@1+ (1,0) [0|65535] "mv"  PC
 SG_ M2P_SysAvgVolt_B8_05 : 16|16@1+ (1,0) [0|65535] "mv"  PC
 SG_ M2P_BMS_Status_B8 : 32|3@1+ (1,0) [0|7] ""  PC
 SG_ M2P_SOC_B8 : 35|10@1+ (0.1,0) [0|102.3] "%"  PC
 SG_ M2P_SOH_B8 : 45|8@1+ (1,0) [0|255] "%"  PC
 SG_ Reserved_05 : 53|11@1+ (1,0) [0|2047] ""  PC

BO_ 2336026262 M2P_SUMDATA53__06: 8 MBMU
 SG_ M2P_SysMinVolt_B8_06 : 0|16@1+ (1,0) [0|65535] "mv"  PC
 SG_ M2P_SysAvgVolt_B8_06 : 16|16@1+ (1,0) [0|65535] "mv"  PC
 SG_ M2P_BMS_Status_B8 : 32|3@1+ (1,0) [0|7] ""  PC
 SG_ M2P_SOC_B8 : 35|10@1+ (0.1,0) [0|102.3] "%"  PC
 SG_ M2P_SOH_B8 : 45|8@1+ (1,0) [0|255] "%"  PC
 SG_ Reserved_06 : 53|11@1+ (1,0) [0|2047] ""  PC

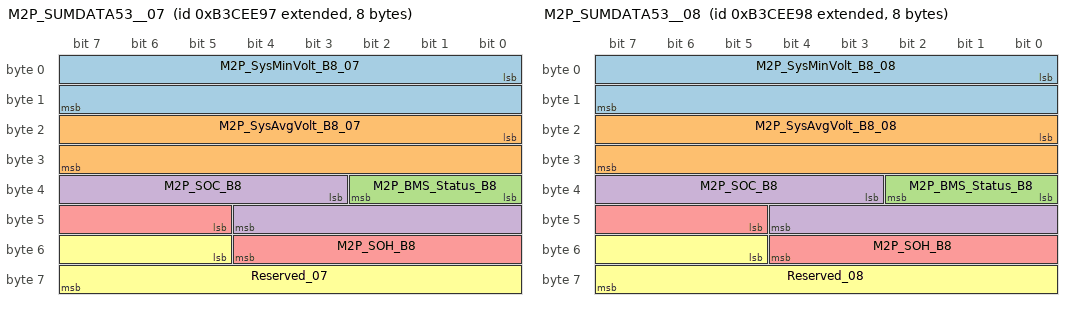
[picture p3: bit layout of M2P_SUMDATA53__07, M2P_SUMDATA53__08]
BO_ 2336026263 M2P_SUMDATA53__07: 8 MBMU
 SG_ M2P_SysMinVolt_B8_07 : 0|16@1+ (1,0) [0|65535] "mv"  PC
 SG_ M2P_SysAvgVolt_B8_07 : 16|16@1+ (1,0) [0|65535] "mv"  PC
 SG_ M2P_BMS_Status_B8 : 32|3@1+ (1,0) [0|7] ""  PC
 SG_ M2P_SOC_B8 : 35|10@1+ (0.1,0) [0|102.3] "%"  PC
 SG_ M2P_SOH_B8 : 45|8@1+ (1,0) [0|255] "%"  PC
 SG_ Reserved_07 : 53|11@1+ (1,0) [0|2047] ""  PC

BO_ 2336026264 M2P_SUMDATA53__08: 8 MBMU
 SG_ M2P_SysMinVolt_B8_08 : 0|16@1+ (1,0) [0|65535] "mv"  PC
 SG_ M2P_SysAvgVolt_B8_08 : 16|16@1+ (1,0) [0|65535] "mv"  PC
 SG_ M2P_BMS_Status_B8 : 32|3@1+ (1,0) [0|7] ""  PC
 SG_ M2P_SOC_B8 : 35|10@1+ (0.1,0) [0|102.3] "%"  PC
 SG_ M2P_SOH_B8 : 45|8@1+ (1,0) [0|255] "%"  PC
 SG_ Reserved_08 : 53|11@1+ (1,0) [0|2047] ""  PC

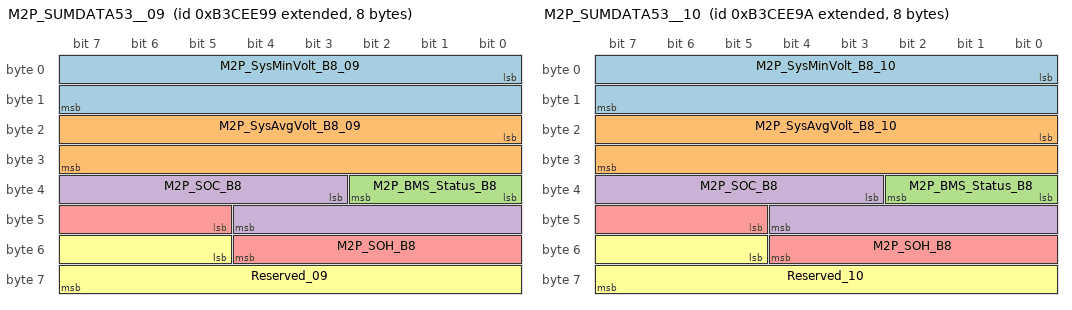
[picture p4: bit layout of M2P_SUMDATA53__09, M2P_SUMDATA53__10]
BO_ 2336026265 M2P_SUMDATA53__09: 8 MBMU
 SG_ M2P_SysMinVolt_B8_09 : 0|16@1+ (1,0) [0|65535] "mv"  PC
 SG_ M2P_SysAvgVolt_B8_09 : 16|16@1+ (1,0) [0|65535] "mv"  PC
 SG_ M2P_BMS_Status_B8 : 32|3@1+ (1,0) [0|7] ""  PC
 SG_ M2P_SOC_B8 : 35|10@1+ (0.1,0) [0|102.3] "%"  PC
 SG_ M2P_SOH_B8 : 45|8@1+ (1,0) [0|255] "%"  PC
 SG_ Reserved_09 : 53|11@1+ (1,0) [0|2047] ""  PC

BO_ 2336026266 M2P_SUMDATA53__10: 8 MBMU
 SG_ M2P_SysMinVolt_B8_10 : 0|16@1+ (1,0) [0|65535] "mv"  PC
 SG_ M2P_SysAvgVolt_B8_10 : 16|16@1+ (1,0) [0|65535] "mv"  PC
 SG_ M2P_BMS_Status_B8 : 32|3@1+ (1,0) [0|7] ""  PC
 SG_ M2P_SOC_B8 : 35|10@1+ (0.1,0) [0|102.3] "%"  PC
 SG_ M2P_SOH_B8 : 45|8@1+ (1,0) [0|255] "%"  PC
 SG_ Reserved_10 : 53|11@1+ (1,0) [0|2047] ""  PC

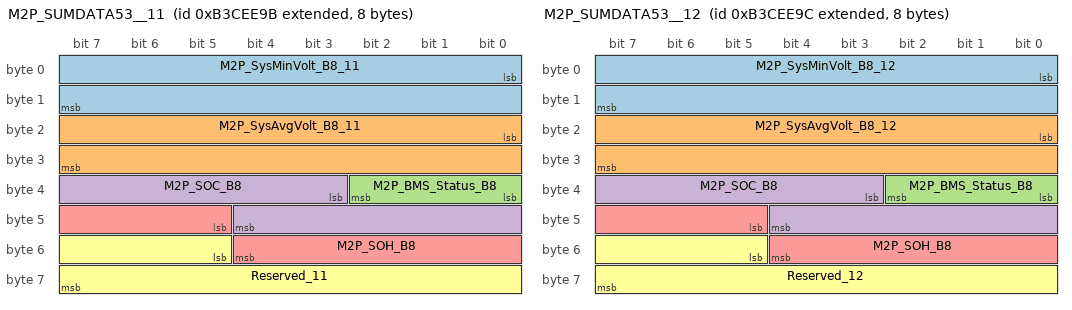
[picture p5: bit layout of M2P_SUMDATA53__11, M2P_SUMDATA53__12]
BO_ 2336026267 M2P_SUMDATA53__11: 8 MBMU
 SG_ M2P_SysMinVolt_B8_11 : 0|16@1+ (1,0) [0|65535] "mv"  PC
 SG_ M2P_SysAvgVolt_B8_11 : 16|16@1+ (1,0) [0|65535] "mv"  PC
 SG_ M2P_BMS_Status_B8 : 32|3@1+ (1,0) [0|7] ""  PC
 SG_ M2P_SOC_B8 : 35|10@1+ (0.1,0) [0|102.3] "%"  PC
 SG_ M2P_SOH_B8 : 45|8@1+ (1,0) [0|255] "%"  PC
 SG_ Reserved_11 : 53|11@1+ (1,0) [0|2047] ""  PC

BO_ 2336026268 M2P_SUMDATA53__12: 8 MBMU
 SG_ M2P_SysMinVolt_B8_12 : 0|16@1+ (1,0) [0|65535] "mv"  PC
 SG_ M2P_SysAvgVolt_B8_12 : 16|16@1+ (1,0) [0|65535] "mv"  PC
 SG_ M2P_BMS_Status_B8 : 32|3@1+ (1,0) [0|7] ""  PC
 SG_ M2P_SOC_B8 : 35|10@1+ (0.1,0) [0|102.3] "%"  PC
 SG_ M2P_SOH_B8 : 45|8@1+ (1,0) [0|255] "%"  PC
 SG_ Reserved_12 : 53|11@1+ (1,0) [0|2047] ""  PC

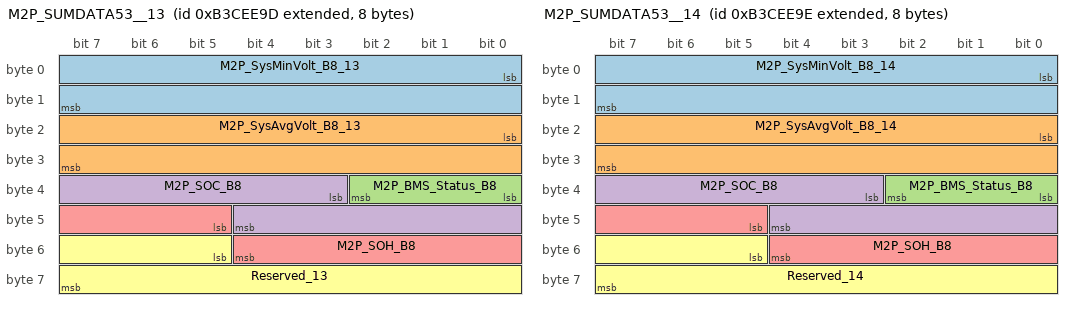
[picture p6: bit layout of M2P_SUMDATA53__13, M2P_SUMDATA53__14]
BO_ 2336026269 M2P_SUMDATA53__13: 8 MBMU
 SG_ M2P_SysMinVolt_B8_13 : 0|16@1+ (1,0) [0|65535] "mv"  PC
 SG_ M2P_SysAvgVolt_B8_13 : 16|16@1+ (1,0) [0|65535] "mv"  PC
 SG_ M2P_BMS_Status_B8 : 32|3@1+ (1,0) [0|7] ""  PC
 SG_ M2P_SOC_B8 : 35|10@1+ (0.1,0) [0|102.3] "%"  PC
 SG_ M2P_SOH_B8 : 45|8@1+ (1,0) [0|255] "%"  PC
 SG_ Reserved_13 : 53|11@1+ (1,0) [0|2047] ""  PC

BO_ 2336026270 M2P_SUMDATA53__14: 8 MBMU
 SG_ M2P_SysMinVolt_B8_14 : 0|16@1+ (1,0) [0|65535] "mv"  PC
 SG_ M2P_SysAvgVolt_B8_14 : 16|16@1+ (1,0) [0|65535] "mv"  PC
 SG_ M2P_BMS_Status_B8 : 32|3@1+ (1,0) [0|7] ""  PC
 SG_ M2P_SOC_B8 : 35|10@1+ (0.1,0) [0|102.3] "%"  PC
 SG_ M2P_SOH_B8 : 45|8@1+ (1,0) [0|255] "%"  PC
 SG_ Reserved_14 : 53|11@1+ (1,0) [0|2047] ""  PC

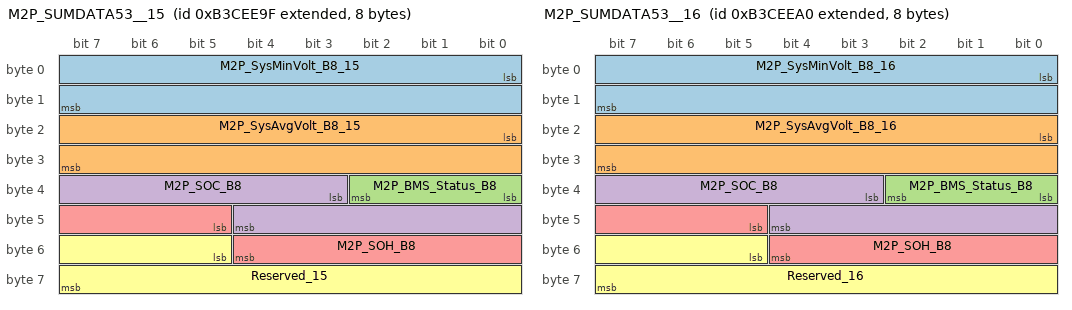
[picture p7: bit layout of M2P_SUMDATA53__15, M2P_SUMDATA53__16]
BO_ 2336026271 M2P_SUMDATA53__15: 8 MBMU
 SG_ M2P_SysMinVolt_B8_15 : 0|16@1+ (1,0) [0|65535] "mv"  PC
 SG_ M2P_SysAvgVolt_B8_15 : 16|16@1+ (1,0) [0|65535] "mv"  PC
 SG_ M2P_BMS_Status_B8 : 32|3@1+ (1,0) [0|7] ""  PC
 SG_ M2P_SOC_B8 : 35|10@1+ (0.1,0) [0|102.3] "%"  PC
 SG_ M2P_SOH_B8 : 45|8@1+ (1,0) [0|255] "%"  PC
 SG_ Reserved_15 : 53|11@1+ (1,0) [0|2047] ""  PC

BO_ 2336026272 M2P_SUMDATA53__16: 8 MBMU
 SG_ M2P_SysMinVolt_B8_16 : 0|16@1+ (1,0) [0|65535] "mv"  PC
 SG_ M2P_SysAvgVolt_B8_16 : 16|16@1+ (1,0) [0|65535] "mv"  PC
 SG_ M2P_BMS_Status_B8 : 32|3@1+ (1,0) [0|7] ""  PC
 SG_ M2P_SOC_B8 : 35|10@1+ (0.1,0) [0|102.3] "%"  PC
 SG_ M2P_SOH_B8 : 45|8@1+ (1,0) [0|255] "%"  PC
 SG_ Reserved_16 : 53|11@1+ (1,0) [0|2047] ""  PC

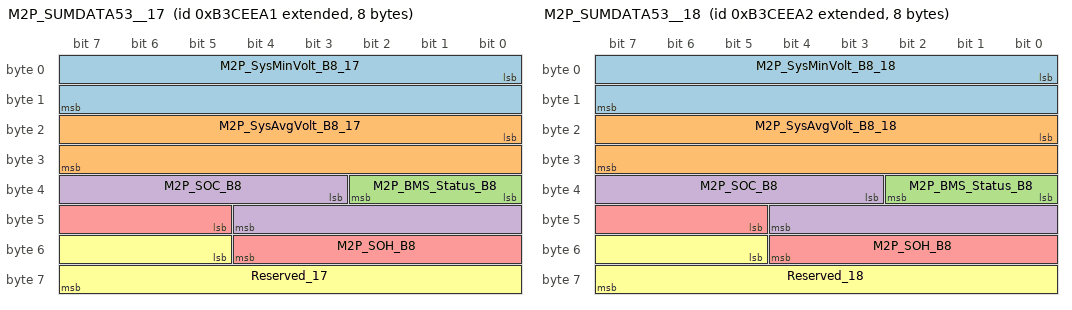
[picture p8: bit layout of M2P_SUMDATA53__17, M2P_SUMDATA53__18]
BO_ 2336026273 M2P_SUMDATA53__17: 8 MBMU
 SG_ M2P_SysMinVolt_B8_17 : 0|16@1+ (1,0) [0|65535] "mv"  PC
 SG_ M2P_SysAvgVolt_B8_17 : 16|16@1+ (1,0) [0|65535] "mv"  PC
 SG_ M2P_BMS_Status_B8 : 32|3@1+ (1,0) [0|7] ""  PC
 SG_ M2P_SOC_B8 : 35|10@1+ (0.1,0) [0|102.3] "%"  PC
 SG_ M2P_SOH_B8 : 45|8@1+ (1,0) [0|255] "%"  PC
 SG_ Reserved_17 : 53|11@1+ (1,0) [0|2047] ""  PC

BO_ 2336026274 M2P_SUMDATA53__18: 8 MBMU
 SG_ M2P_SysMinVolt_B8_18 : 0|16@1+ (1,0) [0|65535] "mv"  PC
 SG_ M2P_SysAvgVolt_B8_18 : 16|16@1+ (1,0) [0|65535] "mv"  PC
 SG_ M2P_BMS_Status_B8 : 32|3@1+ (1,0) [0|7] ""  PC
 SG_ M2P_SOC_B8 : 35|10@1+ (0.1,0) [0|102.3] "%"  PC
 SG_ M2P_SOH_B8 : 45|8@1+ (1,0) [0|255] "%"  PC
 SG_ Reserved_18 : 53|11@1+ (1,0) [0|2047] ""  PC

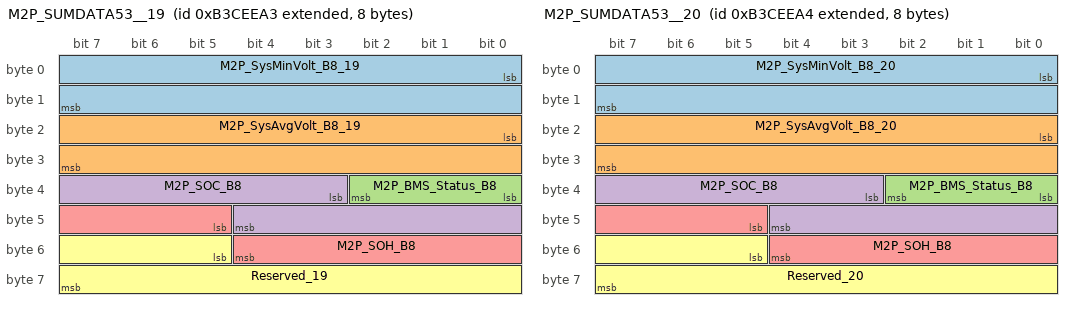
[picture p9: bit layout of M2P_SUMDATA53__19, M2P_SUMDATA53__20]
BO_ 2336026275 M2P_SUMDATA53__19: 8 MBMU
 SG_ M2P_SysMinVolt_B8_19 : 0|16@1+ (1,0) [0|65535] "mv"  PC
 SG_ M2P_SysAvgVolt_B8_19 : 16|16@1+ (1,0) [0|65535] "mv"  PC
 SG_ M2P_BMS_Status_B8 : 32|3@1+ (1,0) [0|7] ""  PC
 SG_ M2P_SOC_B8 : 35|10@1+ (0.1,0) [0|102.3] "%"  PC
 SG_ M2P_SOH_B8 : 45|8@1+ (1,0) [0|255] "%"  PC
 SG_ Reserved_19 : 53|11@1+ (1,0) [0|2047] ""  PC

BO_ 2336026276 M2P_SUMDATA53__20: 8 MBMU
 SG_ M2P_SysMinVolt_B8_20 : 0|16@1+ (1,0) [0|65535] "mv"  PC
 SG_ M2P_SysAvgVolt_B8_20 : 16|16@1+ (1,0) [0|65535] "mv"  PC
 SG_ M2P_BMS_Status_B8 : 32|3@1+ (1,0) [0|7] ""  PC
 SG_ M2P_SOC_B8 : 35|10@1+ (0.1,0) [0|102.3] "%"  PC
 SG_ M2P_SOH_B8 : 45|8@1+ (1,0) [0|255] "%"  PC
 SG_ Reserved_20 : 53|11@1+ (1,0) [0|2047] ""  PC

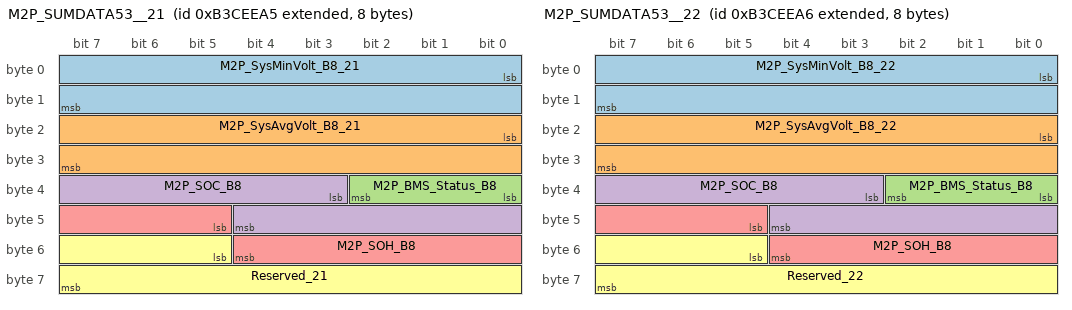
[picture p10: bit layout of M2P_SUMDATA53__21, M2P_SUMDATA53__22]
BO_ 2336026277 M2P_SUMDATA53__21: 8 MBMU
 SG_ M2P_SysMinVolt_B8_21 : 0|16@1+ (1,0) [0|65535] "mv"  PC
 SG_ M2P_SysAvgVolt_B8_21 : 16|16@1+ (1,0) [0|65535] "mv"  PC
 SG_ M2P_BMS_Status_B8 : 32|3@1+ (1,0) [0|7] ""  PC
 SG_ M2P_SOC_B8 : 35|10@1+ (0.1,0) [0|102.3] "%"  PC
 SG_ M2P_SOH_B8 : 45|8@1+ (1,0) [0|255] "%"  PC
 SG_ Reserved_21 : 53|11@1+ (1,0) [0|2047] ""  PC

BO_ 2336026278 M2P_SUMDATA53__22: 8 MBMU
 SG_ M2P_SysMinVolt_B8_22 : 0|16@1+ (1,0) [0|65535] "mv"  PC
 SG_ M2P_SysAvgVolt_B8_22 : 16|16@1+ (1,0) [0|65535] "mv"  PC
 SG_ M2P_BMS_Status_B8 : 32|3@1+ (1,0) [0|7] ""  PC
 SG_ M2P_SOC_B8 : 35|10@1+ (0.1,0) [0|102.3] "%"  PC
 SG_ M2P_SOH_B8 : 45|8@1+ (1,0) [0|255] "%"  PC
 SG_ Reserved_22 : 53|11@1+ (1,0) [0|2047] ""  PC

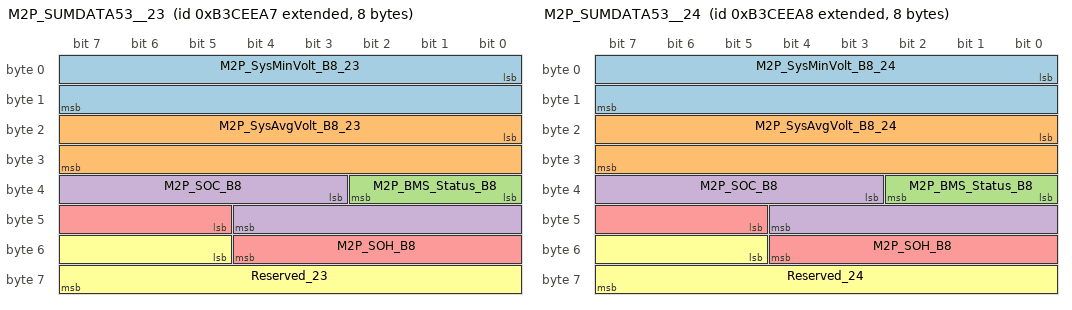
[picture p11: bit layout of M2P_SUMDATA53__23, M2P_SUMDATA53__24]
BO_ 2336026279 M2P_SUMDATA53__23: 8 MBMU
 SG_ M2P_SysMinVolt_B8_23 : 0|16@1+ (1,0) [0|65535] "mv"  PC
 SG_ M2P_SysAvgVolt_B8_23 : 16|16@1+ (1,0) [0|65535] "mv"  PC
 SG_ M2P_BMS_Status_B8 : 32|3@1+ (1,0) [0|7] ""  PC
 SG_ M2P_SOC_B8 : 35|10@1+ (0.1,0) [0|102.3] "%"  PC
 SG_ M2P_SOH_B8 : 45|8@1+ (1,0) [0|255] "%"  PC
 SG_ Reserved_23 : 53|11@1+ (1,0) [0|2047] ""  PC

BO_ 2336026280 M2P_SUMDATA53__24: 8 MBMU
 SG_ M2P_SysMinVolt_B8_24 : 0|16@1+ (1,0) [0|65535] "mv"  PC
 SG_ M2P_SysAvgVolt_B8_24 : 16|16@1+ (1,0) [0|65535] "mv"  PC
 SG_ M2P_BMS_Status_B8 : 32|3@1+ (1,0) [0|7] ""  PC
 SG_ M2P_SOC_B8 : 35|10@1+ (0.1,0) [0|102.3] "%"  PC
 SG_ M2P_SOH_B8 : 45|8@1+ (1,0) [0|255] "%"  PC
 SG_ Reserved_24 : 53|11@1+ (1,0) [0|2047] ""  PC

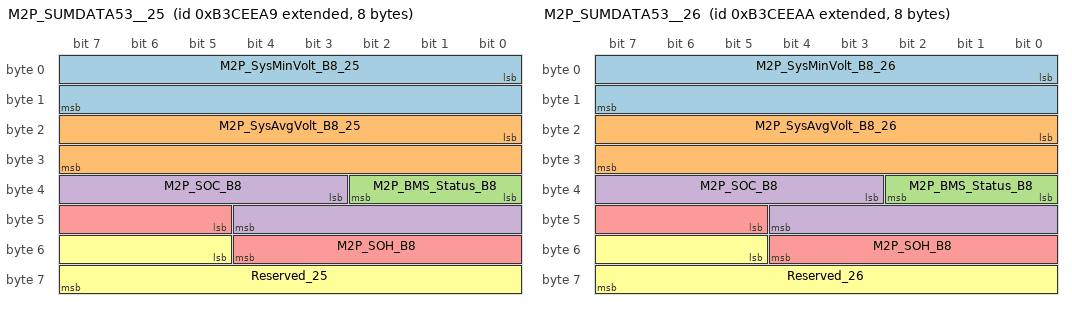
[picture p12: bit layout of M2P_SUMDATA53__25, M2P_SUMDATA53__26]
BO_ 2336026281 M2P_SUMDATA53__25: 8 MBMU
 SG_ M2P_SysMinVolt_B8_25 : 0|16@1+ (1,0) [0|65535] "mv"  PC
 SG_ M2P_SysAvgVolt_B8_25 : 16|16@1+ (1,0) [0|65535] "mv"  PC
 SG_ M2P_BMS_Status_B8 : 32|3@1+ (1,0) [0|7] ""  PC
 SG_ M2P_SOC_B8 : 35|10@1+ (0.1,0) [0|102.3] "%"  PC
 SG_ M2P_SOH_B8 : 45|8@1+ (1,0) [0|255] "%"  PC
 SG_ Reserved_25 : 53|11@1+ (1,0) [0|2047] ""  PC

BO_ 2336026282 M2P_SUMDATA53__26: 8 MBMU
 SG_ M2P_SysMinVolt_B8_26 : 0|16@1+ (1,0) [0|65535] "mv"  PC
 SG_ M2P_SysAvgVolt_B8_26 : 16|16@1+ (1,0) [0|65535] "mv"  PC
 SG_ M2P_BMS_Status_B8 : 32|3@1+ (1,0) [0|7] ""  PC
 SG_ M2P_SOC_B8 : 35|10@1+ (0.1,0) [0|102.3] "%"  PC
 SG_ M2P_SOH_B8 : 45|8@1+ (1,0) [0|255] "%"  PC
 SG_ Reserved_26 : 53|11@1+ (1,0) [0|2047] ""  PC

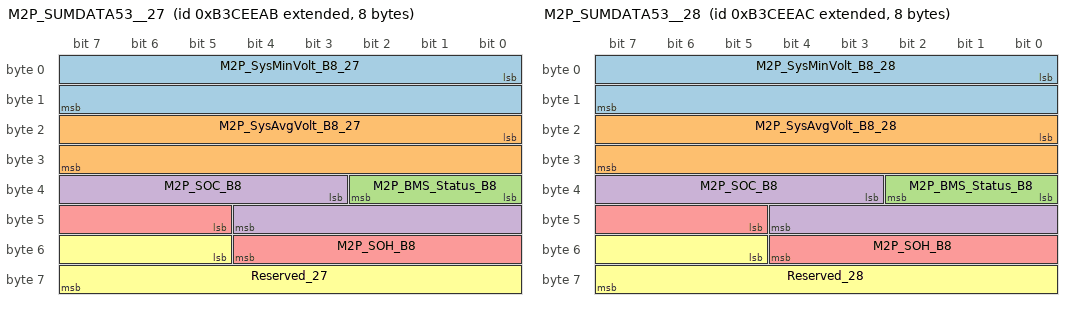
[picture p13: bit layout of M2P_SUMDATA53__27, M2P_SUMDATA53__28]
BO_ 2336026283 M2P_SUMDATA53__27: 8 MBMU
 SG_ M2P_SysMinVolt_B8_27 : 0|16@1+ (1,0) [0|65535] "mv"  PC
 SG_ M2P_SysAvgVolt_B8_27 : 16|16@1+ (1,0) [0|65535] "mv"  PC
 SG_ M2P_BMS_Status_B8 : 32|3@1+ (1,0) [0|7] ""  PC
 SG_ M2P_SOC_B8 : 35|10@1+ (0.1,0) [0|102.3] "%"  PC
 SG_ M2P_SOH_B8 : 45|8@1+ (1,0) [0|255] "%"  PC
 SG_ Reserved_27 : 53|11@1+ (1,0) [0|2047] ""  PC

BO_ 2336026284 M2P_SUMDATA53__28: 8 MBMU
 SG_ M2P_SysMinVolt_B8_28 : 0|16@1+ (1,0) [0|65535] "mv"  PC
 SG_ M2P_SysAvgVolt_B8_28 : 16|16@1+ (1,0) [0|65535] "mv"  PC
 SG_ M2P_BMS_Status_B8 : 32|3@1+ (1,0) [0|7] ""  PC
 SG_ M2P_SOC_B8 : 35|10@1+ (0.1,0) [0|102.3] "%"  PC
 SG_ M2P_SOH_B8 : 45|8@1+ (1,0) [0|255] "%"  PC
 SG_ Reserved_28 : 53|11@1+ (1,0) [0|2047] ""  PC

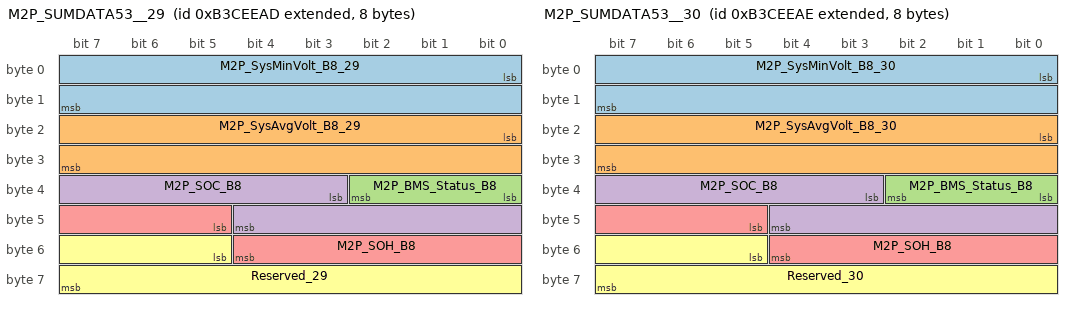
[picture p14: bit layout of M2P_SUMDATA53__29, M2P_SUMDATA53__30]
BO_ 2336026285 M2P_SUMDATA53__29: 8 MBMU
 SG_ M2P_SysMinVolt_B8_29 : 0|16@1+ (1,0) [0|65535] "mv"  PC
 SG_ M2P_SysAvgVolt_B8_29 : 16|16@1+ (1,0) [0|65535] "mv"  PC
 SG_ M2P_BMS_Status_B8 : 32|3@1+ (1,0) [0|7] ""  PC
 SG_ M2P_SOC_B8 : 35|10@1+ (0.1,0) [0|102.3] "%"  PC
 SG_ M2P_SOH_B8 : 45|8@1+ (1,0) [0|255] "%"  PC
 SG_ Reserved_29 : 53|11@1+ (1,0) [0|2047] ""  PC

BO_ 2336026286 M2P_SUMDATA53__30: 8 MBMU
 SG_ M2P_SysMinVolt_B8_30 : 0|16@1+ (1,0) [0|65535] "mv"  PC
 SG_ M2P_SysAvgVolt_B8_30 : 16|16@1+ (1,0) [0|65535] "mv"  PC
 SG_ M2P_BMS_Status_B8 : 32|3@1+ (1,0) [0|7] ""  PC
 SG_ M2P_SOC_B8 : 35|10@1+ (0.1,0) [0|102.3] "%"  PC
 SG_ M2P_SOH_B8 : 45|8@1+ (1,0) [0|255] "%"  PC
 SG_ Reserved_30 : 53|11@1+ (1,0) [0|2047] ""  PC

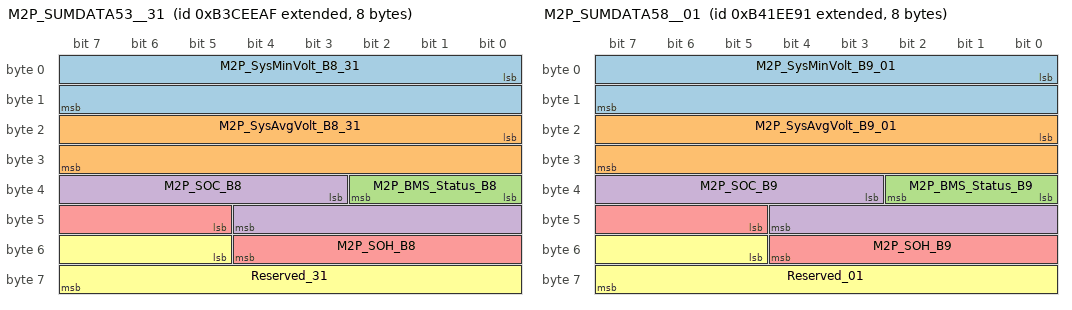
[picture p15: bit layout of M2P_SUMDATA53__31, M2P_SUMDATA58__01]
BO_ 2336026287 M2P_SUMDATA53__31: 8 MBMU
 SG_ M2P_SysMinVolt_B8_31 : 0|16@1+ (1,0) [0|65535] "mv"  PC
 SG_ M2P_SysAvgVolt_B8_31 : 16|16@1+ (1,0) [0|65535] "mv"  PC
 SG_ M2P_BMS_Status_B8 : 32|3@1+ (1,0) [0|7] ""  PC
 SG_ M2P_SOC_B8 : 35|10@1+ (0.1,0) [0|102.3] "%"  PC
 SG_ M2P_SOH_B8 : 45|8@1+ (1,0) [0|255] "%"  PC
 SG_ Reserved_31 : 53|11@1+ (1,0) [0|2047] ""  PC

BO_ 2336091793 M2P_SUMDATA54__01: 8 MBMU
 SG_ M2P_SOE_Charge_B8 : 0|10@1+ (0.1,0) [0|102.3] "%"  PC
 SG_ M2P_SOE_Discharge_B8 : 10|10@1+ (0.1,0) [0|102.3] "%"  PC
 SG_ Reserved_01 : 20|44@1+ (1,0) [0|17592186044415] ""  PC

BO_ 2336091794 M2P_SUMDATA54__02: 8 MBMU
 SG_ M2P_SOE_Charge_B8 : 0|10@1+ (0.1,0) [0|102.3] "%"  PC
 SG_ M2P_SOE_Discharge_B8 : 10|10@1+ (0.1,0) [0|102.3] "%"  PC
 SG_ Reserved_02 : 20|44@1+ (1,0) [0|17592186044415] ""  PC

BO_ 2336091795 M2P_SUMDATA54__03: 8 MBMU
 SG_ M2P_SOE_Charge_B8 : 0|10@1+ (0.1,0) [0|102.3] "%"  PC
 SG_ M2P_SOE_Discharge_B8 : 10|10@1+ (0.1,0) [0|102.3] "%"  PC
 SG_ Reserved_03 : 20|44@1+ (1,0) [0|17592186044415] ""  PC

BO_ 2336091796 M2P_SUMDATA54__04: 8 MBMU
 SG_ M2P_SOE_Charge_B8 : 0|10@1+ (0.1,0) [0|102.3] "%"  PC
 SG_ M2P_SOE_Discharge_B8 : 10|10@1+ (0.1,0) [0|102.3] "%"  PC
 SG_ Reserved_04 : 20|44@1+ (1,0) [0|17592186044415] ""  PC

BO_ 2336091797 M2P_SUMDATA54__05: 8 MBMU
 SG_ M2P_SOE_Charge_B8 : 0|10@1+ (0.1,0) [0|102.3] "%"  PC
 SG_ M2P_SOE_Discharge_B8 : 10|10@1+ (0.1,0) [0|102.3] "%"  PC
 SG_ Reserved_05 : 20|44@1+ (1,0) [0|17592186044415] ""  PC

BO_ 2336091798 M2P_SUMDATA54__06: 8 MBMU
 SG_ M2P_SOE_Charge_B8 : 0|10@1+ (0.1,0) [0|102.3] "%"  PC
 SG_ M2P_SOE_Discharge_B8 : 10|10@1+ (0.1,0) [0|102.3] "%"  PC
 SG_ Reserved_06 : 20|44@1+ (1,0) [0|17592186044415] ""  PC

BO_ 2336091799 M2P_SUMDATA54__07: 8 MBMU
 SG_ M2P_SOE_Charge_B8 : 0|10@1+ (0.1,0) [0|102.3] "%"  PC
 SG_ M2P_SOE_Discharge_B8 : 10|10@1+ (0.1,0) [0|102.3] "%"  PC
 SG_ Reserved_07 : 20|44@1+ (1,0) [0|17592186044415] ""  PC

BO_ 2336091800 M2P_SUMDATA54__08: 8 MBMU
 SG_ M2P_SOE_Charge_B8 : 0|10@1+ (0.1,0) [0|102.3] "%"  PC
 SG_ M2P_SOE_Discharge_B8 : 10|10@1+ (0.1,0) [0|102.3] "%"  PC
 SG_ Reserved_08 : 20|44@1+ (1,0) [0|17592186044415] ""  PC

BO_ 2336091801 M2P_SUMDATA54__09: 8 MBMU
 SG_ M2P_SOE_Charge_B8 : 0|10@1+ (0.1,0) [0|102.3] "%"  PC
 SG_ M2P_SOE_Discharge_B8 : 10|10@1+ (0.1,0) [0|102.3] "%"  PC
 SG_ Reserved_09 : 20|44@1+ (1,0) [0|17592186044415] ""  PC

BO_ 2336091802 M2P_SUMDATA54__10: 8 MBMU
 SG_ M2P_SOE_Charge_B8 : 0|10@1+ (0.1,0) [0|102.3] "%"  PC
 SG_ M2P_SOE_Discharge_B8 : 10|10@1+ (0.1,0) [0|102.3] "%"  PC
 SG_ Reserved_10 : 20|44@1+ (1,0) [0|17592186044415] ""  PC

BO_ 2336091803 M2P_SUMDATA54__11: 8 MBMU
 SG_ M2P_SOE_Charge_B8 : 0|10@1+ (0.1,0) [0|102.3] "%"  PC
 SG_ M2P_SOE_Discharge_B8 : 10|10@1+ (0.1,0) [0|102.3] "%"  PC
 SG_ Reserved_11 : 20|44@1+ (1,0) [0|17592186044415] ""  PC

BO_ 2336091804 M2P_SUMDATA54__12: 8 MBMU
 SG_ M2P_SOE_Charge_B8 : 0|10@1+ (0.1,0) [0|102.3] "%"  PC
 SG_ M2P_SOE_Discharge_B8 : 10|10@1+ (0.1,0) [0|102.3] "%"  PC
 SG_ Reserved_12 : 20|44@1+ (1,0) [0|17592186044415] ""  PC

BO_ 2336091805 M2P_SUMDATA54__13: 8 MBMU
 SG_ M2P_SOE_Charge_B8 : 0|10@1+ (0.1,0) [0|102.3] "%"  PC
 SG_ M2P_SOE_Discharge_B8 : 10|10@1+ (0.1,0) [0|102.3] "%"  PC
 SG_ Reserved_13 : 20|44@1+ (1,0) [0|17592186044415] ""  PC

BO_ 2336091806 M2P_SUMDATA54__14: 8 MBMU
 SG_ M2P_SOE_Charge_B8 : 0|10@1+ (0.1,0) [0|102.3] "%"  PC
 SG_ M2P_SOE_Discharge_B8 : 10|10@1+ (0.1,0) [0|102.3] "%"  PC
 SG_ Reserved_14 : 20|44@1+ (1,0) [0|17592186044415] ""  PC

BO_ 2336091807 M2P_SUMDATA54__15: 8 MBMU
 SG_ M2P_SOE_Charge_B8 : 0|10@1+ (0.1,0) [0|102.3] "%"  PC
 SG_ M2P_SOE_Discharge_B8 : 10|10@1+ (0.1,0) [0|102.3] "%"  PC
 SG_ Reserved_15 : 20|44@1+ (1,0) [0|17592186044415] ""  PC

BO_ 2336091808 M2P_SUMDATA54__16: 8 MBMU
 SG_ M2P_SOE_Charge_B8 : 0|10@1+ (0.1,0) [0|102.3] "%"  PC
 SG_ M2P_SOE_Discharge_B8 : 10|10@1+ (0.1,0) [0|102.3] "%"  PC
 SG_ Reserved_16 : 20|44@1+ (1,0) [0|17592186044415] ""  PC

BO_ 2336091809 M2P_SUMDATA54__17: 8 MBMU
 SG_ M2P_SOE_Charge_B8 : 0|10@1+ (0.1,0) [0|102.3] "%"  PC
 SG_ M2P_SOE_Discharge_B8 : 10|10@1+ (0.1,0) [0|102.3] "%"  PC
 SG_ Reserved_17 : 20|44@1+ (1,0) [0|17592186044415] ""  PC

BO_ 2336091810 M2P_SUMDATA54__18: 8 MBMU
 SG_ M2P_SOE_Charge_B8 : 0|10@1+ (0.1,0) [0|102.3] "%"  PC
 SG_ M2P_SOE_Discharge_B8 : 10|10@1+ (0.1,0) [0|102.3] "%"  PC
 SG_ Reserved_18 : 20|44@1+ (1,0) [0|17592186044415] ""  PC

BO_ 2336091811 M2P_SUMDATA54__19: 8 MBMU
 SG_ M2P_SOE_Charge_B8 : 0|10@1+ (0.1,0) [0|102.3] "%"  PC
 SG_ M2P_SOE_Discharge_B8 : 10|10@1+ (0.1,0) [0|102.3] "%"  PC
 SG_ Reserved_19 : 20|44@1+ (1,0) [0|17592186044415] ""  PC

BO_ 2336091812 M2P_SUMDATA54__20: 8 MBMU
 SG_ M2P_SOE_Charge_B8 : 0|10@1+ (0.1,0) [0|102.3] "%"  PC
 SG_ M2P_SOE_Discharge_B8 : 10|10@1+ (0.1,0) [0|102.3] "%"  PC
 SG_ Reserved_20 : 20|44@1+ (1,0) [0|17592186044415] ""  PC

BO_ 2336091813 M2P_SUMDATA54__21: 8 MBMU
 SG_ M2P_SOE_Charge_B8 : 0|10@1+ (0.1,0) [0|102.3] "%"  PC
 SG_ M2P_SOE_Discharge_B8 : 10|10@1+ (0.1,0) [0|102.3] "%"  PC
 SG_ Reserved_21 : 20|44@1+ (1,0) [0|17592186044415] ""  PC

BO_ 2336091814 M2P_SUMDATA54__22: 8 MBMU
 SG_ M2P_SOE_Charge_B8 : 0|10@1+ (0.1,0) [0|102.3] "%"  PC
 SG_ M2P_SOE_Discharge_B8 : 10|10@1+ (0.1,0) [0|102.3] "%"  PC
 SG_ Reserved_22 : 20|44@1+ (1,0) [0|17592186044415] ""  PC

BO_ 2336091815 M2P_SUMDATA54__23: 8 MBMU
 SG_ M2P_SOE_Charge_B8 : 0|10@1+ (0.1,0) [0|102.3] "%"  PC
 SG_ M2P_SOE_Discharge_B8 : 10|10@1+ (0.1,0) [0|102.3] "%"  PC
 SG_ Reserved_23 : 20|44@1+ (1,0) [0|17592186044415] ""  PC

BO_ 2336091816 M2P_SUMDATA54__24: 8 MBMU
 SG_ M2P_SOE_Charge_B8 : 0|10@1+ (0.1,0) [0|102.3] "%"  PC
 SG_ M2P_SOE_Discharge_B8 : 10|10@1+ (0.1,0) [0|102.3] "%"  PC
 SG_ Reserved_24 : 20|44@1+ (1,0) [0|17592186044415] ""  PC

BO_ 2336091817 M2P_SUMDATA54__25: 8 MBMU
 SG_ M2P_SOE_Charge_B8 : 0|10@1+ (0.1,0) [0|102.3] "%"  PC
 SG_ M2P_SOE_Discharge_B8 : 10|10@1+ (0.1,0) [0|102.3] "%"  PC
 SG_ Reserved_25 : 20|44@1+ (1,0) [0|17592186044415] ""  PC

BO_ 2336091818 M2P_SUMDATA54__26: 8 MBMU
 SG_ M2P_SOE_Charge_B8 : 0|10@1+ (0.1,0) [0|102.3] "%"  PC
 SG_ M2P_SOE_Discharge_B8 : 10|10@1+ (0.1,0) [0|102.3] "%"  PC
 SG_ Reserved_26 : 20|44@1+ (1,0) [0|17592186044415] ""  PC

BO_ 2336091819 M2P_SUMDATA54__27: 8 MBMU
 SG_ M2P_SOE_Charge_B8 : 0|10@1+ (0.1,0) [0|102.3] "%"  PC
 SG_ M2P_SOE_Discharge_B8 : 10|10@1+ (0.1,0) [0|102.3] "%"  PC
 SG_ Reserved_27 : 20|44@1+ (1,0) [0|17592186044415] ""  PC

BO_ 2336091820 M2P_SUMDATA54__28: 8 MBMU
 SG_ M2P_SOE_Charge_B8 : 0|10@1+ (0.1,0) [0|102.3] "%"  PC
 SG_ M2P_SOE_Discharge_B8 : 10|10@1+ (0.1,0) [0|102.3] "%"  PC
 SG_ Reserved_28 : 20|44@1+ (1,0) [0|17592186044415] ""  PC

BO_ 2336091821 M2P_SUMDATA54__29: 8 MBMU
 SG_ M2P_SOE_Charge_B8 : 0|10@1+ (0.1,0) [0|102.3] "%"  PC
 SG_ M2P_SOE_Discharge_B8 : 10|10@1+ (0.1,0) [0|102.3] "%"  PC
 SG_ Reserved_29 : 20|44@1+ (1,0) [0|17592186044415] ""  PC

BO_ 2336091822 M2P_SUMDATA54__30: 8 MBMU
 SG_ M2P_SOE_Charge_B8 : 0|10@1+ (0.1,0) [0|102.3] "%"  PC
 SG_ M2P_SOE_Discharge_B8 : 10|10@1+ (0.1,0) [0|102.3] "%"  PC
 SG_ Reserved_30 : 20|44@1+ (1,0) [0|17592186044415] ""  PC

BO_ 2336091823 M2P_SUMDATA54__31: 8 MBMU
 SG_ M2P_SOE_Charge_B8 : 0|10@1+ (0.1,0) [0|102.3] "%"  PC
 SG_ M2P_SOE_Discharge_B8 : 10|10@1+ (0.1,0) [0|102.3] "%"  PC
 SG_ Reserved_31 : 20|44@1+ (1,0) [0|17592186044415] ""  PC

BO_ 2336157329 M2P_SUMDATA55__01: 8 MBMU
 SG_ M2P_Measure_Vol_B9_01 : 0|16@1+ (0.1,0) [0|6553.5] "V"  PC,SBMU
 SG_ M2P_Current_B9_01 : 16|16@1+ (1,-20000) [-20000|45535] "A"  PC,SBMU
 SG_ M2P_PermitMaxCharge_I_B9_01 : 32|16@1+ (1,-20000) [-20000|45535] "A"  PC
 SG_ M2P_PermitMaxDisCharge_I_B9_01 : 48|16@1+ (1,-20000) [-20000|45535] "A"  PC

BO_ 2336157330 M2P_SUMDATA55__02: 8 MBMU
 SG_ M2P_Measure_Vol_B9_02 : 0|16@1+ (0.1,0) [0|6553.5] "V"  PC,SBMU
 SG_ M2P_Current_B9_02 : 16|16@1+ (1,-20000) [-20000|45535] "A"  PC,SBMU
 SG_ M2P_PermitMaxCharge_I_B9_02 : 32|16@1+ (1,-20000) [-20000|45535] "A"  PC
 SG_ M2P_PermitMaxDisCharge_I_B9_02 : 48|16@1+ (1,-20000) [-20000|45535] "A"  PC

BO_ 2336157331 M2P_SUMDATA55__03: 8 MBMU
 SG_ M2P_Measure_Vol_B9_03 : 0|16@1+ (0.1,0) [0|6553.5] "V"  PC,SBMU
 SG_ M2P_Current_B9_03 : 16|16@1+ (1,-20000) [-20000|45535] "A"  PC,SBMU
 SG_ M2P_PermitMaxCharge_I_B9_03 : 32|16@1+ (1,-20000) [-20000|45535] "A"  PC
 SG_ M2P_PermitMaxDisCharge_I_B9_03 : 48|16@1+ (1,-20000) [-20000|45535] "A"  PC

BO_ 2336157332 M2P_SUMDATA55__04: 8 MBMU
 SG_ M2P_Measure_Vol_B9_04 : 0|16@1+ (0.1,0) [0|6553.5] "V"  PC,SBMU
 SG_ M2P_Current_B9_04 : 16|16@1+ (1,-20000) [-20000|45535] "A"  PC,SBMU
 SG_ M2P_PermitMaxCharge_I_B9_04 : 32|16@1+ (1,-20000) [-20000|45535] "A"  PC
 SG_ M2P_PermitMaxDisCharge_I_B9_04 : 48|16@1+ (1,-20000) [-20000|45535] "A"  PC

BO_ 2336157333 M2P_SUMDATA55__05: 8 MBMU
 SG_ M2P_Measure_Vol_B9_05 : 0|16@1+ (0.1,0) [0|6553.5] "V"  PC,SBMU
 SG_ M2P_Current_B9_05 : 16|16@1+ (1,-20000) [-20000|45535] "A"  PC,SBMU
 SG_ M2P_PermitMaxCharge_I_B9_05 : 32|16@1+ (1,-20000) [-20000|45535] "A"  PC
 SG_ M2P_PermitMaxDisCharge_I_B9_05 : 48|16@1+ (1,-20000) [-20000|45535] "A"  PC

BO_ 2336157334 M2P_SUMDATA55__06: 8 MBMU
 SG_ M2P_Measure_Vol_B9_06 : 0|16@1+ (0.1,0) [0|6553.5] "V"  PC,SBMU
 SG_ M2P_Current_B9_06 : 16|16@1+ (1,-20000) [-20000|45535] "A"  PC,SBMU
 SG_ M2P_PermitMaxCharge_I_B9_06 : 32|16@1+ (1,-20000) [-20000|45535] "A"  PC
 SG_ M2P_PermitMaxDisCharge_I_B9_06 : 48|16@1+ (1,-20000) [-20000|45535] "A"  PC

BO_ 2336157335 M2P_SUMDATA55__07: 8 MBMU
 SG_ M2P_Measure_Vol_B9_07 : 0|16@1+ (0.1,0) [0|6553.5] "V"  PC,SBMU
 SG_ M2P_Current_B9_07 : 16|16@1+ (1,-20000) [-20000|45535] "A"  PC,SBMU
 SG_ M2P_PermitMaxCharge_I_B9_07 : 32|16@1+ (1,-20000) [-20000|45535] "A"  PC
 SG_ M2P_PermitMaxDisCharge_I_B9_07 : 48|16@1+ (1,-20000) [-20000|45535] "A"  PC

BO_ 2336157336 M2P_SUMDATA55__08: 8 MBMU
 SG_ M2P_Measure_Vol_B9_08 : 0|16@1+ (0.1,0) [0|6553.5] "V"  PC,SBMU
 SG_ M2P_Current_B9_08 : 16|16@1+ (1,-20000) [-20000|45535] "A"  PC,SBMU
 SG_ M2P_PermitMaxCharge_I_B9_08 : 32|16@1+ (1,-20000) [-20000|45535] "A"  PC
 SG_ M2P_PermitMaxDisCharge_I_B9_08 : 48|16@1+ (1,-20000) [-20000|45535] "A"  PC

BO_ 2336157337 M2P_SUMDATA55__09: 8 MBMU
 SG_ M2P_Measure_Vol_B9_09 : 0|16@1+ (0.1,0) [0|6553.5] "V"  PC,SBMU
 SG_ M2P_Current_B9_09 : 16|16@1+ (1,-20000) [-20000|45535] "A"  PC,SBMU
 SG_ M2P_PermitMaxCharge_I_B9_09 : 32|16@1+ (1,-20000) [-20000|45535] "A"  PC
 SG_ M2P_PermitMaxDisCharge_I_B9_09 : 48|16@1+ (1,-20000) [-20000|45535] "A"  PC

BO_ 2336157338 M2P_SUMDATA55__10: 8 MBMU
 SG_ M2P_Measure_Vol_B9_10 : 0|16@1+ (0.1,0) [0|6553.5] "V"  PC,SBMU
 SG_ M2P_Current_B9_10 : 16|16@1+ (1,-20000) [-20000|45535] "A"  PC,SBMU
 SG_ M2P_PermitMaxCharge_I_B9_10 : 32|16@1+ (1,-20000) [-20000|45535] "A"  PC
 SG_ M2P_PermitMaxDisCharge_I_B9_10 : 48|16@1+ (1,-20000) [-20000|45535] "A"  PC

BO_ 2336157339 M2P_SUMDATA55__11: 8 MBMU
 SG_ M2P_Measure_Vol_B9_11 : 0|16@1+ (0.1,0) [0|6553.5] "V"  PC,SBMU
 SG_ M2P_Current_B9_11 : 16|16@1+ (1,-20000) [-20000|45535] "A"  PC,SBMU
 SG_ M2P_PermitMaxCharge_I_B9_11 : 32|16@1+ (1,-20000) [-20000|45535] "A"  PC
 SG_ M2P_PermitMaxDisCharge_I_B9_11 : 48|16@1+ (1,-20000) [-20000|45535] "A"  PC

BO_ 2336157340 M2P_SUMDATA55__12: 8 MBMU
 SG_ M2P_Measure_Vol_B9_12 : 0|16@1+ (0.1,0) [0|6553.5] "V"  PC,SBMU
 SG_ M2P_Current_B9_12 : 16|16@1+ (1,-20000) [-20000|45535] "A"  PC,SBMU
 SG_ M2P_PermitMaxCharge_I_B9_12 : 32|16@1+ (1,-20000) [-20000|45535] "A"  PC
 SG_ M2P_PermitMaxDisCharge_I_B9_12 : 48|16@1+ (1,-20000) [-20000|45535] "A"  PC

BO_ 2336157341 M2P_SUMDATA55__13: 8 MBMU
 SG_ M2P_Measure_Vol_B9_13 : 0|16@1+ (0.1,0) [0|6553.5] "V"  PC,SBMU
 SG_ M2P_Current_B9_13 : 16|16@1+ (1,-20000) [-20000|45535] "A"  PC,SBMU
 SG_ M2P_PermitMaxCharge_I_B9_13 : 32|16@1+ (1,-20000) [-20000|45535] "A"  PC
 SG_ M2P_PermitMaxDisCharge_I_B9_13 : 48|16@1+ (1,-20000) [-20000|45535] "A"  PC

BO_ 2336157342 M2P_SUMDATA55__14: 8 MBMU
 SG_ M2P_Measure_Vol_B9_14 : 0|16@1+ (0.1,0) [0|6553.5] "V"  PC,SBMU
 SG_ M2P_Current_B9_14 : 16|16@1+ (1,-20000) [-20000|45535] "A"  PC,SBMU
 SG_ M2P_PermitMaxCharge_I_B9_14 : 32|16@1+ (1,-20000) [-20000|45535] "A"  PC
 SG_ M2P_PermitMaxDisCharge_I_B9_14 : 48|16@1+ (1,-20000) [-20000|45535] "A"  PC

BO_ 2336157343 M2P_SUMDATA55__15: 8 MBMU
 SG_ M2P_Measure_Vol_B9_15 : 0|16@1+ (0.1,0) [0|6553.5] "V"  PC,SBMU
 SG_ M2P_Current_B9_15 : 16|16@1+ (1,-20000) [-20000|45535] "A"  PC,SBMU
 SG_ M2P_PermitMaxCharge_I_B9_15 : 32|16@1+ (1,-20000) [-20000|45535] "A"  PC
 SG_ M2P_PermitMaxDisCharge_I_B9_15 : 48|16@1+ (1,-20000) [-20000|45535] "A"  PC

BO_ 2336157344 M2P_SUMDATA55__16: 8 MBMU
 SG_ M2P_Measure_Vol_B9_16 : 0|16@1+ (0.1,0) [0|6553.5] "V"  PC,SBMU
 SG_ M2P_Current_B9_16 : 16|16@1+ (1,-20000) [-20000|45535] "A"  PC,SBMU
 SG_ M2P_PermitMaxCharge_I_B9_16 : 32|16@1+ (1,-20000) [-20000|45535] "A"  PC
 SG_ M2P_PermitMaxDisCharge_I_B9_16 : 48|16@1+ (1,-20000) [-20000|45535] "A"  PC

BO_ 2336157345 M2P_SUMDATA55__17: 8 MBMU
 SG_ M2P_Measure_Vol_B9_17 : 0|16@1+ (0.1,0) [0|6553.5] "V"  PC,SBMU
 SG_ M2P_Current_B9_17 : 16|16@1+ (1,-20000) [-20000|45535] "A"  PC,SBMU
 SG_ M2P_PermitMaxCharge_I_B9_17 : 32|16@1+ (1,-20000) [-20000|45535] "A"  PC
 SG_ M2P_PermitMaxDisCharge_I_B9_17 : 48|16@1+ (1,-20000) [-20000|45535] "A"  PC

BO_ 2336157346 M2P_SUMDATA55__18: 8 MBMU
 SG_ M2P_Measure_Vol_B9_18 : 0|16@1+ (0.1,0) [0|6553.5] "V"  PC,SBMU
 SG_ M2P_Current_B9_18 : 16|16@1+ (1,-20000) [-20000|45535] "A"  PC,SBMU
 SG_ M2P_PermitMaxCharge_I_B9_18 : 32|16@1+ (1,-20000) [-20000|45535] "A"  PC
 SG_ M2P_PermitMaxDisCharge_I_B9_18 : 48|16@1+ (1,-20000) [-20000|45535] "A"  PC

BO_ 2336157347 M2P_SUMDATA55__19: 8 MBMU
 SG_ M2P_Measure_Vol_B9_19 : 0|16@1+ (0.1,0) [0|6553.5] "V"  PC,SBMU
 SG_ M2P_Current_B9_19 : 16|16@1+ (1,-20000) [-20000|45535] "A"  PC,SBMU
 SG_ M2P_PermitMaxCharge_I_B9_19 : 32|16@1+ (1,-20000) [-20000|45535] "A"  PC
 SG_ M2P_PermitMaxDisCharge_I_B9_19 : 48|16@1+ (1,-20000) [-20000|45535] "A"  PC

BO_ 2336157348 M2P_SUMDATA55__20: 8 MBMU
 SG_ M2P_Measure_Vol_B9_20 : 0|16@1+ (0.1,0) [0|6553.5] "V"  PC,SBMU
 SG_ M2P_Current_B9_20 : 16|16@1+ (1,-20000) [-20000|45535] "A"  PC,SBMU
 SG_ M2P_PermitMaxCharge_I_B9_20 : 32|16@1+ (1,-20000) [-20000|45535] "A"  PC
 SG_ M2P_PermitMaxDisCharge_I_B9_20 : 48|16@1+ (1,-20000) [-20000|45535] "A"  PC

BO_ 2336157349 M2P_SUMDATA55__21: 8 MBMU
 SG_ M2P_Measure_Vol_B9_21 : 0|16@1+ (0.1,0) [0|6553.5] "V"  PC,SBMU
 SG_ M2P_Current_B9_21 : 16|16@1+ (1,-20000) [-20000|45535] "A"  PC,SBMU
 SG_ M2P_PermitMaxCharge_I_B9_21 : 32|16@1+ (1,-20000) [-20000|45535] "A"  PC
 SG_ M2P_PermitMaxDisCharge_I_B9_21 : 48|16@1+ (1,-20000) [-20000|45535] "A"  PC

BO_ 2336157350 M2P_SUMDATA55__22: 8 MBMU
 SG_ M2P_Measure_Vol_B9_22 : 0|16@1+ (0.1,0) [0|6553.5] "V"  PC,SBMU
 SG_ M2P_Current_B9_22 : 16|16@1+ (1,-20000) [-20000|45535] "A"  PC,SBMU
 SG_ M2P_PermitMaxCharge_I_B9_22 : 32|16@1+ (1,-20000) [-20000|45535] "A"  PC
 SG_ M2P_PermitMaxDisCharge_I_B9_22 : 48|16@1+ (1,-20000) [-20000|45535] "A"  PC

BO_ 2336157351 M2P_SUMDATA55__23: 8 MBMU
 SG_ M2P_Measure_Vol_B9_23 : 0|16@1+ (0.1,0) [0|6553.5] "V"  PC,SBMU
 SG_ M2P_Current_B9_23 : 16|16@1+ (1,-20000) [-20000|45535] "A"  PC,SBMU
 SG_ M2P_PermitMaxCharge_I_B9_23 : 32|16@1+ (1,-20000) [-20000|45535] "A"  PC
 SG_ M2P_PermitMaxDisCharge_I_B9_23 : 48|16@1+ (1,-20000) [-20000|45535] "A"  PC

BO_ 2336157352 M2P_SUMDATA55__24: 8 MBMU
 SG_ M2P_Measure_Vol_B9_24 : 0|16@1+ (0.1,0) [0|6553.5] "V"  PC,SBMU
 SG_ M2P_Current_B9_24 : 16|16@1+ (1,-20000) [-20000|45535] "A"  PC,SBMU
 SG_ M2P_PermitMaxCharge_I_B9_24 : 32|16@1+ (1,-20000) [-20000|45535] "A"  PC
 SG_ M2P_PermitMaxDisCharge_I_B9_24 : 48|16@1+ (1,-20000) [-20000|45535] "A"  PC

BO_ 2336157353 M2P_SUMDATA55__25: 8 MBMU
 SG_ M2P_Measure_Vol_B9_25 : 0|16@1+ (0.1,0) [0|6553.5] "V"  PC,SBMU
 SG_ M2P_Current_B9_25 : 16|16@1+ (1,-20000) [-20000|45535] "A"  PC,SBMU
 SG_ M2P_PermitMaxCharge_I_B9_25 : 32|16@1+ (1,-20000) [-20000|45535] "A"  PC
 SG_ M2P_PermitMaxDisCharge_I_B9_25 : 48|16@1+ (1,-20000) [-20000|45535] "A"  PC

BO_ 2336157354 M2P_SUMDATA55__26: 8 MBMU
 SG_ M2P_Measure_Vol_B9_26 : 0|16@1+ (0.1,0) [0|6553.5] "V"  PC,SBMU
 SG_ M2P_Current_B9_26 : 16|16@1+ (1,-20000) [-20000|45535] "A"  PC,SBMU
 SG_ M2P_PermitMaxCharge_I_B9_26 : 32|16@1+ (1,-20000) [-20000|45535] "A"  PC
 SG_ M2P_PermitMaxDisCharge_I_B9_26 : 48|16@1+ (1,-20000) [-20000|45535] "A"  PC

BO_ 2336157355 M2P_SUMDATA55__27: 8 MBMU
 SG_ M2P_Measure_Vol_B9_27 : 0|16@1+ (0.1,0) [0|6553.5] "V"  PC,SBMU
 SG_ M2P_Current_B9_27 : 16|16@1+ (1,-20000) [-20000|45535] "A"  PC,SBMU
 SG_ M2P_PermitMaxCharge_I_B9_27 : 32|16@1+ (1,-20000) [-20000|45535] "A"  PC
 SG_ M2P_PermitMaxDisCharge_I_B9_27 : 48|16@1+ (1,-20000) [-20000|45535] "A"  PC

BO_ 2336157356 M2P_SUMDATA55__28: 8 MBMU
 SG_ M2P_Measure_Vol_B9_28 : 0|16@1+ (0.1,0) [0|6553.5] "V"  PC,SBMU
 SG_ M2P_Current_B9_28 : 16|16@1+ (1,-20000) [-20000|45535] "A"  PC,SBMU
 SG_ M2P_PermitMaxCharge_I_B9_28 : 32|16@1+ (1,-20000) [-20000|45535] "A"  PC
 SG_ M2P_PermitMaxDisCharge_I_B9_28 : 48|16@1+ (1,-20000) [-20000|45535] "A"  PC

BO_ 2336157357 M2P_SUMDATA55__29: 8 MBMU
 SG_ M2P_Measure_Vol_B9_29 : 0|16@1+ (0.1,0) [0|6553.5] "V"  PC,SBMU
 SG_ M2P_Current_B9_29 : 16|16@1+ (1,-20000) [-20000|45535] "A"  PC,SBMU
 SG_ M2P_PermitMaxCharge_I_B9_29 : 32|16@1+ (1,-20000) [-20000|45535] "A"  PC
 SG_ M2P_PermitMaxDisCharge_I_B9_29 : 48|16@1+ (1,-20000) [-20000|45535] "A"  PC

BO_ 2336157358 M2P_SUMDATA55__30: 8 MBMU
 SG_ M2P_Measure_Vol_B9_30 : 0|16@1+ (0.1,0) [0|6553.5] "V"  PC,SBMU
 SG_ M2P_Current_B9_30 : 16|16@1+ (1,-20000) [-20000|45535] "A"  PC,SBMU
 SG_ M2P_PermitMaxCharge_I_B9_30 : 32|16@1+ (1,-20000) [-20000|45535] "A"  PC
 SG_ M2P_PermitMaxDisCharge_I_B9_30 : 48|16@1+ (1,-20000) [-20000|45535] "A"  PC

BO_ 2336157359 M2P_SUMDATA55__31: 8 MBMU
 SG_ M2P_Measure_Vol_B9_31 : 0|16@1+ (0.1,0) [0|6553.5] "V"  PC,SBMU
 SG_ M2P_Current_B9_31 : 16|16@1+ (1,-20000) [-20000|45535] "A"  PC,SBMU
 SG_ M2P_PermitMaxCharge_I_B9_31 : 32|16@1+ (1,-20000) [-20000|45535] "A"  PC
 SG_ M2P_PermitMaxDisCharge_I_B9_31 : 48|16@1+ (1,-20000) [-20000|45535] "A"  PC

BO_ 2336222865 M2P_SUMDATA56__01: 8 MBMU
 SG_ M2P_PermitMaxVolt_B9_01 : 0|16@1+ (0.1,0) [0|6553.5] "V"  PC
 SG_ M2P_PermitMinVolt_B9_01 : 16|16@1+ (0.1,0) [0|6553.5] "V"  PC
 SG_ M2P_PermitMaxPow_Chg_B9_01 : 32|16@1+ (1,-20000) [-20000|45535] "Kw"  PC
 SG_ M2P_PermitMaxPow_DisChg_B9_01 : 48|16@1+ (1,-20000) [-20000|45535] "Kw"  PC

BO_ 2336222866 M2P_SUMDATA56__02: 8 MBMU
 SG_ M2P_PermitMaxVolt_B9_02 : 0|16@1+ (0.1,0) [0|6553.5] "V"  PC
 SG_ M2P_PermitMinVolt_B9_02 : 16|16@1+ (0.1,0) [0|6553.5] "V"  PC
 SG_ M2P_PermitMaxPow_Chg_B9_02 : 32|16@1+ (1,-20000) [-20000|45535] "Kw"  PC
 SG_ M2P_PermitMaxPow_DisChg_B9_02 : 48|16@1+ (1,-20000) [-20000|45535] "Kw"  PC

BO_ 2336222867 M2P_SUMDATA56__03: 8 MBMU
 SG_ M2P_PermitMaxVolt_B9_03 : 0|16@1+ (0.1,0) [0|6553.5] "V"  PC
 SG_ M2P_PermitMinVolt_B9_03 : 16|16@1+ (0.1,0) [0|6553.5] "V"  PC
 SG_ M2P_PermitMaxPow_Chg_B9_03 : 32|16@1+ (1,-20000) [-20000|45535] "Kw"  PC
 SG_ M2P_PermitMaxPow_DisChg_B9_03 : 48|16@1+ (1,-20000) [-20000|45535] "Kw"  PC

BO_ 2336222868 M2P_SUMDATA56__04: 8 MBMU
 SG_ M2P_PermitMaxVolt_B9_04 : 0|16@1+ (0.1,0) [0|6553.5] "V"  PC
 SG_ M2P_PermitMinVolt_B9_04 : 16|16@1+ (0.1,0) [0|6553.5] "V"  PC
 SG_ M2P_PermitMaxPow_Chg_B9_04 : 32|16@1+ (1,-20000) [-20000|45535] "Kw"  PC
 SG_ M2P_PermitMaxPow_DisChg_B9_04 : 48|16@1+ (1,-20000) [-20000|45535] "Kw"  PC

BO_ 2336222869 M2P_SUMDATA56__05: 8 MBMU
 SG_ M2P_PermitMaxVolt_B9_05 : 0|16@1+ (0.1,0) [0|6553.5] "V"  PC
 SG_ M2P_PermitMinVolt_B9_05 : 16|16@1+ (0.1,0) [0|6553.5] "V"  PC
 SG_ M2P_PermitMaxPow_Chg_B9_05 : 32|16@1+ (1,-20000) [-20000|45535] "Kw"  PC
 SG_ M2P_PermitMaxPow_DisChg_B9_05 : 48|16@1+ (1,-20000) [-20000|45535] "Kw"  PC

BO_ 2336222870 M2P_SUMDATA56__06: 8 MBMU
 SG_ M2P_PermitMaxVolt_B9_06 : 0|16@1+ (0.1,0) [0|6553.5] "V"  PC
 SG_ M2P_PermitMinVolt_B9_06 : 16|16@1+ (0.1,0) [0|6553.5] "V"  PC
 SG_ M2P_PermitMaxPow_Chg_B9_06 : 32|16@1+ (1,-20000) [-20000|45535] "Kw"  PC
 SG_ M2P_PermitMaxPow_DisChg_B9_06 : 48|16@1+ (1,-20000) [-20000|45535] "Kw"  PC

BO_ 2336222871 M2P_SUMDATA56__07: 8 MBMU
 SG_ M2P_PermitMaxVolt_B9_07 : 0|16@1+ (0.1,0) [0|6553.5] "V"  PC
 SG_ M2P_PermitMinVolt_B9_07 : 16|16@1+ (0.1,0) [0|6553.5] "V"  PC
 SG_ M2P_PermitMaxPow_Chg_B9_07 : 32|16@1+ (1,-20000) [-20000|45535] "Kw"  PC
 SG_ M2P_PermitMaxPow_DisChg_B9_07 : 48|16@1+ (1,-20000) [-20000|45535] "Kw"  PC

BO_ 2336222872 M2P_SUMDATA56__08: 8 MBMU
 SG_ M2P_PermitMaxVolt_B9_08 : 0|16@1+ (0.1,0) [0|6553.5] "V"  PC
 SG_ M2P_PermitMinVolt_B9_08 : 16|16@1+ (0.1,0) [0|6553.5] "V"  PC
 SG_ M2P_PermitMaxPow_Chg_B9_08 : 32|16@1+ (1,-20000) [-20000|45535] "Kw"  PC
 SG_ M2P_PermitMaxPow_DisChg_B9_08 : 48|16@1+ (1,-20000) [-20000|45535] "Kw"  PC

BO_ 2336222873 M2P_SUMDATA56__09: 8 MBMU
 SG_ M2P_PermitMaxVolt_B9_09 : 0|16@1+ (0.1,0) [0|6553.5] "V"  PC
 SG_ M2P_PermitMinVolt_B9_09 : 16|16@1+ (0.1,0) [0|6553.5] "V"  PC
 SG_ M2P_PermitMaxPow_Chg_B9_09 : 32|16@1+ (1,-20000) [-20000|45535] "Kw"  PC
 SG_ M2P_PermitMaxPow_DisChg_B9_09 : 48|16@1+ (1,-20000) [-20000|45535] "Kw"  PC

BO_ 2336222874 M2P_SUMDATA56__10: 8 MBMU
 SG_ M2P_PermitMaxVolt_B9_10 : 0|16@1+ (0.1,0) [0|6553.5] "V"  PC
 SG_ M2P_PermitMinVolt_B9_10 : 16|16@1+ (0.1,0) [0|6553.5] "V"  PC
 SG_ M2P_PermitMaxPow_Chg_B9_10 : 32|16@1+ (1,-20000) [-20000|45535] "Kw"  PC
 SG_ M2P_PermitMaxPow_DisChg_B9_10 : 48|16@1+ (1,-20000) [-20000|45535] "Kw"  PC

BO_ 2336222875 M2P_SUMDATA56__11: 8 MBMU
 SG_ M2P_PermitMaxVolt_B9_11 : 0|16@1+ (0.1,0) [0|6553.5] "V"  PC
 SG_ M2P_PermitMinVolt_B9_11 : 16|16@1+ (0.1,0) [0|6553.5] "V"  PC
 SG_ M2P_PermitMaxPow_Chg_B9_11 : 32|16@1+ (1,-20000) [-20000|45535] "Kw"  PC
 SG_ M2P_PermitMaxPow_DisChg_B9_11 : 48|16@1+ (1,-20000) [-20000|45535] "Kw"  PC

BO_ 2336222876 M2P_SUMDATA56__12: 8 MBMU
 SG_ M2P_PermitMaxVolt_B9_12 : 0|16@1+ (0.1,0) [0|6553.5] "V"  PC
 SG_ M2P_PermitMinVolt_B9_12 : 16|16@1+ (0.1,0) [0|6553.5] "V"  PC
 SG_ M2P_PermitMaxPow_Chg_B9_12 : 32|16@1+ (1,-20000) [-20000|45535] "Kw"  PC
 SG_ M2P_PermitMaxPow_DisChg_B9_12 : 48|16@1+ (1,-20000) [-20000|45535] "Kw"  PC

BO_ 2336222877 M2P_SUMDATA56__13: 8 MBMU
 SG_ M2P_PermitMaxVolt_B9_13 : 0|16@1+ (0.1,0) [0|6553.5] "V"  PC
 SG_ M2P_PermitMinVolt_B9_13 : 16|16@1+ (0.1,0) [0|6553.5] "V"  PC
 SG_ M2P_PermitMaxPow_Chg_B9_13 : 32|16@1+ (1,-20000) [-20000|45535] "Kw"  PC
 SG_ M2P_PermitMaxPow_DisChg_B9_13 : 48|16@1+ (1,-20000) [-20000|45535] "Kw"  PC

BO_ 2336222878 M2P_SUMDATA56__14: 8 MBMU
 SG_ M2P_PermitMaxVolt_B9_14 : 0|16@1+ (0.1,0) [0|6553.5] "V"  PC
 SG_ M2P_PermitMinVolt_B9_14 : 16|16@1+ (0.1,0) [0|6553.5] "V"  PC
 SG_ M2P_PermitMaxPow_Chg_B9_14 : 32|16@1+ (1,-20000) [-20000|45535] "Kw"  PC
 SG_ M2P_PermitMaxPow_DisChg_B9_14 : 48|16@1+ (1,-20000) [-20000|45535] "Kw"  PC

BO_ 2336222879 M2P_SUMDATA56__15: 8 MBMU
 SG_ M2P_PermitMaxVolt_B9_15 : 0|16@1+ (0.1,0) [0|6553.5] "V"  PC
 SG_ M2P_PermitMinVolt_B9_15 : 16|16@1+ (0.1,0) [0|6553.5] "V"  PC
 SG_ M2P_PermitMaxPow_Chg_B9_15 : 32|16@1+ (1,-20000) [-20000|45535] "Kw"  PC
 SG_ M2P_PermitMaxPow_DisChg_B9_15 : 48|16@1+ (1,-20000) [-20000|45535] "Kw"  PC

BO_ 2336222880 M2P_SUMDATA56__16: 8 MBMU
 SG_ M2P_PermitMaxVolt_B9_16 : 0|16@1+ (0.1,0) [0|6553.5] "V"  PC
 SG_ M2P_PermitMinVolt_B9_16 : 16|16@1+ (0.1,0) [0|6553.5] "V"  PC
 SG_ M2P_PermitMaxPow_Chg_B9_16 : 32|16@1+ (1,-20000) [-20000|45535] "Kw"  PC
 SG_ M2P_PermitMaxPow_DisChg_B9_16 : 48|16@1+ (1,-20000) [-20000|45535] "Kw"  PC

BO_ 2336222881 M2P_SUMDATA56__17: 8 MBMU
 SG_ M2P_PermitMaxVolt_B9_17 : 0|16@1+ (0.1,0) [0|6553.5] "V"  PC
 SG_ M2P_PermitMinVolt_B9_17 : 16|16@1+ (0.1,0) [0|6553.5] "V"  PC
 SG_ M2P_PermitMaxPow_Chg_B9_17 : 32|16@1+ (1,-20000) [-20000|45535] "Kw"  PC
 SG_ M2P_PermitMaxPow_DisChg_B9_17 : 48|16@1+ (1,-20000) [-20000|45535] "Kw"  PC

BO_ 2336222882 M2P_SUMDATA56__18: 8 MBMU
 SG_ M2P_PermitMaxVolt_B9_18 : 0|16@1+ (0.1,0) [0|6553.5] "V"  PC
 SG_ M2P_PermitMinVolt_B9_18 : 16|16@1+ (0.1,0) [0|6553.5] "V"  PC
 SG_ M2P_PermitMaxPow_Chg_B9_18 : 32|16@1+ (1,-20000) [-20000|45535] "Kw"  PC
 SG_ M2P_PermitMaxPow_DisChg_B9_18 : 48|16@1+ (1,-20000) [-20000|45535] "Kw"  PC

BO_ 2336222883 M2P_SUMDATA56__19: 8 MBMU
 SG_ M2P_PermitMaxVolt_B9_19 : 0|16@1+ (0.1,0) [0|6553.5] "V"  PC
 SG_ M2P_PermitMinVolt_B9_19 : 16|16@1+ (0.1,0) [0|6553.5] "V"  PC
 SG_ M2P_PermitMaxPow_Chg_B9_19 : 32|16@1+ (1,-20000) [-20000|45535] "Kw"  PC
 SG_ M2P_PermitMaxPow_DisChg_B9_19 : 48|16@1+ (1,-20000) [-20000|45535] "Kw"  PC

BO_ 2336222884 M2P_SUMDATA56__20: 8 MBMU
 SG_ M2P_PermitMaxVolt_B9_20 : 0|16@1+ (0.1,0) [0|6553.5] "V"  PC
 SG_ M2P_PermitMinVolt_B9_20 : 16|16@1+ (0.1,0) [0|6553.5] "V"  PC
 SG_ M2P_PermitMaxPow_Chg_B9_20 : 32|16@1+ (1,-20000) [-20000|45535] "Kw"  PC
 SG_ M2P_PermitMaxPow_DisChg_B9_20 : 48|16@1+ (1,-20000) [-20000|45535] "Kw"  PC

BO_ 2336222885 M2P_SUMDATA56__21: 8 MBMU
 SG_ M2P_PermitMaxVolt_B9_21 : 0|16@1+ (0.1,0) [0|6553.5] "V"  PC
 SG_ M2P_PermitMinVolt_B9_21 : 16|16@1+ (0.1,0) [0|6553.5] "V"  PC
 SG_ M2P_PermitMaxPow_Chg_B9_21 : 32|16@1+ (1,-20000) [-20000|45535] "Kw"  PC
 SG_ M2P_PermitMaxPow_DisChg_B9_21 : 48|16@1+ (1,-20000) [-20000|45535] "Kw"  PC

BO_ 2336222886 M2P_SUMDATA56__22: 8 MBMU
 SG_ M2P_PermitMaxVolt_B9_22 : 0|16@1+ (0.1,0) [0|6553.5] "V"  PC
 SG_ M2P_PermitMinVolt_B9_22 : 16|16@1+ (0.1,0) [0|6553.5] "V"  PC
 SG_ M2P_PermitMaxPow_Chg_B9_22 : 32|16@1+ (1,-20000) [-20000|45535] "Kw"  PC
 SG_ M2P_PermitMaxPow_DisChg_B9_22 : 48|16@1+ (1,-20000) [-20000|45535] "Kw"  PC

BO_ 2336222887 M2P_SUMDATA56__23: 8 MBMU
 SG_ M2P_PermitMaxVolt_B9_23 : 0|16@1+ (0.1,0) [0|6553.5] "V"  PC
 SG_ M2P_PermitMinVolt_B9_23 : 16|16@1+ (0.1,0) [0|6553.5] "V"  PC
 SG_ M2P_PermitMaxPow_Chg_B9_23 : 32|16@1+ (1,-20000) [-20000|45535] "Kw"  PC
 SG_ M2P_PermitMaxPow_DisChg_B9_23 : 48|16@1+ (1,-20000) [-20000|45535] "Kw"  PC

BO_ 2336222888 M2P_SUMDATA56__24: 8 MBMU
 SG_ M2P_PermitMaxVolt_B9_24 : 0|16@1+ (0.1,0) [0|6553.5] "V"  PC
 SG_ M2P_PermitMinVolt_B9_24 : 16|16@1+ (0.1,0) [0|6553.5] "V"  PC
 SG_ M2P_PermitMaxPow_Chg_B9_24 : 32|16@1+ (1,-20000) [-20000|45535] "Kw"  PC
 SG_ M2P_PermitMaxPow_DisChg_B9_24 : 48|16@1+ (1,-20000) [-20000|45535] "Kw"  PC

BO_ 2336222889 M2P_SUMDATA56__25: 8 MBMU
 SG_ M2P_PermitMaxVolt_B9_25 : 0|16@1+ (0.1,0) [0|6553.5] "V"  PC
 SG_ M2P_PermitMinVolt_B9_25 : 16|16@1+ (0.1,0) [0|6553.5] "V"  PC
 SG_ M2P_PermitMaxPow_Chg_B9_25 : 32|16@1+ (1,-20000) [-20000|45535] "Kw"  PC
 SG_ M2P_PermitMaxPow_DisChg_B9_25 : 48|16@1+ (1,-20000) [-20000|45535] "Kw"  PC

BO_ 2336222890 M2P_SUMDATA56__26: 8 MBMU
 SG_ M2P_PermitMaxVolt_B9_26 : 0|16@1+ (0.1,0) [0|6553.5] "V"  PC
 SG_ M2P_PermitMinVolt_B9_26 : 16|16@1+ (0.1,0) [0|6553.5] "V"  PC
 SG_ M2P_PermitMaxPow_Chg_B9_26 : 32|16@1+ (1,-20000) [-20000|45535] "Kw"  PC
 SG_ M2P_PermitMaxPow_DisChg_B9_26 : 48|16@1+ (1,-20000) [-20000|45535] "Kw"  PC

BO_ 2336222891 M2P_SUMDATA56__27: 8 MBMU
 SG_ M2P_PermitMaxVolt_B9_27 : 0|16@1+ (0.1,0) [0|6553.5] "V"  PC
 SG_ M2P_PermitMinVolt_B9_27 : 16|16@1+ (0.1,0) [0|6553.5] "V"  PC
 SG_ M2P_PermitMaxPow_Chg_B9_27 : 32|16@1+ (1,-20000) [-20000|45535] "Kw"  PC
 SG_ M2P_PermitMaxPow_DisChg_B9_27 : 48|16@1+ (1,-20000) [-20000|45535] "Kw"  PC

BO_ 2336222892 M2P_SUMDATA56__28: 8 MBMU
 SG_ M2P_PermitMaxVolt_B9_28 : 0|16@1+ (0.1,0) [0|6553.5] "V"  PC
 SG_ M2P_PermitMinVolt_B9_28 : 16|16@1+ (0.1,0) [0|6553.5] "V"  PC
 SG_ M2P_PermitMaxPow_Chg_B9_28 : 32|16@1+ (1,-20000) [-20000|45535] "Kw"  PC
 SG_ M2P_PermitMaxPow_DisChg_B9_28 : 48|16@1+ (1,-20000) [-20000|45535] "Kw"  PC

BO_ 2336222893 M2P_SUMDATA56__29: 8 MBMU
 SG_ M2P_PermitMaxVolt_B9_29 : 0|16@1+ (0.1,0) [0|6553.5] "V"  PC
 SG_ M2P_PermitMinVolt_B9_29 : 16|16@1+ (0.1,0) [0|6553.5] "V"  PC
 SG_ M2P_PermitMaxPow_Chg_B9_29 : 32|16@1+ (1,-20000) [-20000|45535] "Kw"  PC
 SG_ M2P_PermitMaxPow_DisChg_B9_29 : 48|16@1+ (1,-20000) [-20000|45535] "Kw"  PC

BO_ 2336222894 M2P_SUMDATA56__30: 8 MBMU
 SG_ M2P_PermitMaxVolt_B9_30 : 0|16@1+ (0.1,0) [0|6553.5] "V"  PC
 SG_ M2P_PermitMinVolt_B9_30 : 16|16@1+ (0.1,0) [0|6553.5] "V"  PC
 SG_ M2P_PermitMaxPow_Chg_B9_30 : 32|16@1+ (1,-20000) [-20000|45535] "Kw"  PC
 SG_ M2P_PermitMaxPow_DisChg_B9_30 : 48|16@1+ (1,-20000) [-20000|45535] "Kw"  PC

BO_ 2336222895 M2P_SUMDATA56__31: 8 MBMU
 SG_ M2P_PermitMaxVolt_B9_31 : 0|16@1+ (0.1,0) [0|6553.5] "V"  PC
 SG_ M2P_PermitMinVolt_B9_31 : 16|16@1+ (0.1,0) [0|6553.5] "V"  PC
 SG_ M2P_PermitMaxPow_Chg_B9_31 : 32|16@1+ (1,-20000) [-20000|45535] "Kw"  PC
 SG_ M2P_PermitMaxPow_DisChg_B9_31 : 48|16@1+ (1,-20000) [-20000|45535] "Kw"  PC

BO_ 2336288401 M2P_SUMDATA57__01: 8 MBMU
 SG_ M2P_Power_B9_01 : 0|16@1+ (1,-20000) [-20000|45535] "Kw"  PC
 SG_ M2P_SysremEngy_Chg_B9_01 : 16|16@1+ (1,0) [0|65535] "Kwh"  PC
 SG_ M2P_SysremEngy_DisChg_B9_01 : 32|16@1+ (1,0) [0|65535] "Kwh"  PC
 SG_ M2P_SysMaxVolt_B9_01 : 48|16@1+ (1,0) [0|65535] "mv"  PC

BO_ 2336288402 M2P_SUMDATA57__02: 8 MBMU
 SG_ M2P_Power_B9_02 : 0|16@1+ (1,-20000) [-20000|45535] "Kw"  PC
 SG_ M2P_SysremEngy_Chg_B9_02 : 16|16@1+ (1,0) [0|65535] "Kwh"  PC
 SG_ M2P_SysremEngy_DisChg_B9_02 : 32|16@1+ (1,0) [0|65535] "Kwh"  PC
 SG_ M2P_SysMaxVolt_B9_02 : 48|16@1+ (1,0) [0|65535] "mv"  PC

BO_ 2336288403 M2P_SUMDATA57__03: 8 MBMU
 SG_ M2P_Power_B9_03 : 0|16@1+ (1,-20000) [-20000|45535] "Kw"  PC
 SG_ M2P_SysremEngy_Chg_B9_03 : 16|16@1+ (1,0) [0|65535] "Kwh"  PC
 SG_ M2P_SysremEngy_DisChg_B9_03 : 32|16@1+ (1,0) [0|65535] "Kwh"  PC
 SG_ M2P_SysMaxVolt_B9_03 : 48|16@1+ (1,0) [0|65535] "mv"  PC

BO_ 2336288404 M2P_SUMDATA57__04: 8 MBMU
 SG_ M2P_Power_B9_04 : 0|16@1+ (1,-20000) [-20000|45535] "Kw"  PC
 SG_ M2P_SysremEngy_Chg_B9_04 : 16|16@1+ (1,0) [0|65535] "Kwh"  PC
 SG_ M2P_SysremEngy_DisChg_B9_04 : 32|16@1+ (1,0) [0|65535] "Kwh"  PC
 SG_ M2P_SysMaxVolt_B9_04 : 48|16@1+ (1,0) [0|65535] "mv"  PC

BO_ 2336288405 M2P_SUMDATA57__05: 8 MBMU
 SG_ M2P_Power_B9_05 : 0|16@1+ (1,-20000) [-20000|45535] "Kw"  PC
 SG_ M2P_SysremEngy_Chg_B9_05 : 16|16@1+ (1,0) [0|65535] "Kwh"  PC
 SG_ M2P_SysremEngy_DisChg_B9_05 : 32|16@1+ (1,0) [0|65535] "Kwh"  PC
 SG_ M2P_SysMaxVolt_B9_05 : 48|16@1+ (1,0) [0|65535] "mv"  PC

BO_ 2336288406 M2P_SUMDATA57__06: 8 MBMU
 SG_ M2P_Power_B9_06 : 0|16@1+ (1,-20000) [-20000|45535] "Kw"  PC
 SG_ M2P_SysremEngy_Chg_B9_06 : 16|16@1+ (1,0) [0|65535] "Kwh"  PC
 SG_ M2P_SysremEngy_DisChg_B9_06 : 32|16@1+ (1,0) [0|65535] "Kwh"  PC
 SG_ M2P_SysMaxVolt_B9_06 : 48|16@1+ (1,0) [0|65535] "mv"  PC

BO_ 2336288407 M2P_SUMDATA57__07: 8 MBMU
 SG_ M2P_Power_B9_07 : 0|16@1+ (1,-20000) [-20000|45535] "Kw"  PC
 SG_ M2P_SysremEngy_Chg_B9_07 : 16|16@1+ (1,0) [0|65535] "Kwh"  PC
 SG_ M2P_SysremEngy_DisChg_B9_07 : 32|16@1+ (1,0) [0|65535] "Kwh"  PC
 SG_ M2P_SysMaxVolt_B9_07 : 48|16@1+ (1,0) [0|65535] "mv"  PC

BO_ 2336288408 M2P_SUMDATA57__08: 8 MBMU
 SG_ M2P_Power_B9_08 : 0|16@1+ (1,-20000) [-20000|45535] "Kw"  PC
 SG_ M2P_SysremEngy_Chg_B9_08 : 16|16@1+ (1,0) [0|65535] "Kwh"  PC
 SG_ M2P_SysremEngy_DisChg_B9_08 : 32|16@1+ (1,0) [0|65535] "Kwh"  PC
 SG_ M2P_SysMaxVolt_B9_08 : 48|16@1+ (1,0) [0|65535] "mv"  PC

BO_ 2336288409 M2P_SUMDATA57__09: 8 MBMU
 SG_ M2P_Power_B9_09 : 0|16@1+ (1,-20000) [-20000|45535] "Kw"  PC
 SG_ M2P_SysremEngy_Chg_B9_09 : 16|16@1+ (1,0) [0|65535] "Kwh"  PC
 SG_ M2P_SysremEngy_DisChg_B9_09 : 32|16@1+ (1,0) [0|65535] "Kwh"  PC
 SG_ M2P_SysMaxVolt_B9_09 : 48|16@1+ (1,0) [0|65535] "mv"  PC

BO_ 2336288410 M2P_SUMDATA57__10: 8 MBMU
 SG_ M2P_Power_B9_10 : 0|16@1+ (1,-20000) [-20000|45535] "Kw"  PC
 SG_ M2P_SysremEngy_Chg_B9_10 : 16|16@1+ (1,0) [0|65535] "Kwh"  PC
 SG_ M2P_SysremEngy_DisChg_B9_10 : 32|16@1+ (1,0) [0|65535] "Kwh"  PC
 SG_ M2P_SysMaxVolt_B9_10 : 48|16@1+ (1,0) [0|65535] "mv"  PC

BO_ 2336288411 M2P_SUMDATA57__11: 8 MBMU
 SG_ M2P_Power_B9_11 : 0|16@1+ (1,-20000) [-20000|45535] "Kw"  PC
 SG_ M2P_SysremEngy_Chg_B9_11 : 16|16@1+ (1,0) [0|65535] "Kwh"  PC
 SG_ M2P_SysremEngy_DisChg_B9_11 : 32|16@1+ (1,0) [0|65535] "Kwh"  PC
 SG_ M2P_SysMaxVolt_B9_11 : 48|16@1+ (1,0) [0|65535] "mv"  PC

BO_ 2336288412 M2P_SUMDATA57__12: 8 MBMU
 SG_ M2P_Power_B9_12 : 0|16@1+ (1,-20000) [-20000|45535] "Kw"  PC
 SG_ M2P_SysremEngy_Chg_B9_12 : 16|16@1+ (1,0) [0|65535] "Kwh"  PC
 SG_ M2P_SysremEngy_DisChg_B9_12 : 32|16@1+ (1,0) [0|65535] "Kwh"  PC
 SG_ M2P_SysMaxVolt_B9_12 : 48|16@1+ (1,0) [0|65535] "mv"  PC

BO_ 2336288413 M2P_SUMDATA57__13: 8 MBMU
 SG_ M2P_Power_B9_13 : 0|16@1+ (1,-20000) [-20000|45535] "Kw"  PC
 SG_ M2P_SysremEngy_Chg_B9_13 : 16|16@1+ (1,0) [0|65535] "Kwh"  PC
 SG_ M2P_SysremEngy_DisChg_B9_13 : 32|16@1+ (1,0) [0|65535] "Kwh"  PC
 SG_ M2P_SysMaxVolt_B9_13 : 48|16@1+ (1,0) [0|65535] "mv"  PC

BO_ 2336288414 M2P_SUMDATA57__14: 8 MBMU
 SG_ M2P_Power_B9_14 : 0|16@1+ (1,-20000) [-20000|45535] "Kw"  PC
 SG_ M2P_SysremEngy_Chg_B9_14 : 16|16@1+ (1,0) [0|65535] "Kwh"  PC
 SG_ M2P_SysremEngy_DisChg_B9_14 : 32|16@1+ (1,0) [0|65535] "Kwh"  PC
 SG_ M2P_SysMaxVolt_B9_14 : 48|16@1+ (1,0) [0|65535] "mv"  PC

BO_ 2336288415 M2P_SUMDATA57__15: 8 MBMU
 SG_ M2P_Power_B9_15 : 0|16@1+ (1,-20000) [-20000|45535] "Kw"  PC
 SG_ M2P_SysremEngy_Chg_B9_15 : 16|16@1+ (1,0) [0|65535] "Kwh"  PC
 SG_ M2P_SysremEngy_DisChg_B9_15 : 32|16@1+ (1,0) [0|65535] "Kwh"  PC
 SG_ M2P_SysMaxVolt_B9_15 : 48|16@1+ (1,0) [0|65535] "mv"  PC

BO_ 2336288416 M2P_SUMDATA57__16: 8 MBMU
 SG_ M2P_Power_B9_16 : 0|16@1+ (1,-20000) [-20000|45535] "Kw"  PC
 SG_ M2P_SysremEngy_Chg_B9_16 : 16|16@1+ (1,0) [0|65535] "Kwh"  PC
 SG_ M2P_SysremEngy_DisChg_B9_16 : 32|16@1+ (1,0) [0|65535] "Kwh"  PC
 SG_ M2P_SysMaxVolt_B9_16 : 48|16@1+ (1,0) [0|65535] "mv"  PC

BO_ 2336288417 M2P_SUMDATA57__17: 8 MBMU
 SG_ M2P_Power_B9_17 : 0|16@1+ (1,-20000) [-20000|45535] "Kw"  PC
 SG_ M2P_SysremEngy_Chg_B9_17 : 16|16@1+ (1,0) [0|65535] "Kwh"  PC
 SG_ M2P_SysremEngy_DisChg_B9_17 : 32|16@1+ (1,0) [0|65535] "Kwh"  PC
 SG_ M2P_SysMaxVolt_B9_17 : 48|16@1+ (1,0) [0|65535] "mv"  PC

BO_ 2336288418 M2P_SUMDATA57__18: 8 MBMU
 SG_ M2P_Power_B9_18 : 0|16@1+ (1,-20000) [-20000|45535] "Kw"  PC
 SG_ M2P_SysremEngy_Chg_B9_18 : 16|16@1+ (1,0) [0|65535] "Kwh"  PC
 SG_ M2P_SysremEngy_DisChg_B9_18 : 32|16@1+ (1,0) [0|65535] "Kwh"  PC
 SG_ M2P_SysMaxVolt_B9_18 : 48|16@1+ (1,0) [0|65535] "mv"  PC

BO_ 2336288419 M2P_SUMDATA57__19: 8 MBMU
 SG_ M2P_Power_B9_19 : 0|16@1+ (1,-20000) [-20000|45535] "Kw"  PC
 SG_ M2P_SysremEngy_Chg_B9_19 : 16|16@1+ (1,0) [0|65535] "Kwh"  PC
 SG_ M2P_SysremEngy_DisChg_B9_19 : 32|16@1+ (1,0) [0|65535] "Kwh"  PC
 SG_ M2P_SysMaxVolt_B9_19 : 48|16@1+ (1,0) [0|65535] "mv"  PC

BO_ 2336288420 M2P_SUMDATA57__20: 8 MBMU
 SG_ M2P_Power_B9_20 : 0|16@1+ (1,-20000) [-20000|45535] "Kw"  PC
 SG_ M2P_SysremEngy_Chg_B9_20 : 16|16@1+ (1,0) [0|65535] "Kwh"  PC
 SG_ M2P_SysremEngy_DisChg_B9_20 : 32|16@1+ (1,0) [0|65535] "Kwh"  PC
 SG_ M2P_SysMaxVolt_B9_20 : 48|16@1+ (1,0) [0|65535] "mv"  PC

BO_ 2336288421 M2P_SUMDATA57__21: 8 MBMU
 SG_ M2P_Power_B9_21 : 0|16@1+ (1,-20000) [-20000|45535] "Kw"  PC
 SG_ M2P_SysremEngy_Chg_B9_21 : 16|16@1+ (1,0) [0|65535] "Kwh"  PC
 SG_ M2P_SysremEngy_DisChg_B9_21 : 32|16@1+ (1,0) [0|65535] "Kwh"  PC
 SG_ M2P_SysMaxVolt_B9_21 : 48|16@1+ (1,0) [0|65535] "mv"  PC

BO_ 2336288422 M2P_SUMDATA57__22: 8 MBMU
 SG_ M2P_Power_B9_22 : 0|16@1+ (1,-20000) [-20000|45535] "Kw"  PC
 SG_ M2P_SysremEngy_Chg_B9_22 : 16|16@1+ (1,0) [0|65535] "Kwh"  PC
 SG_ M2P_SysremEngy_DisChg_B9_22 : 32|16@1+ (1,0) [0|65535] "Kwh"  PC
 SG_ M2P_SysMaxVolt_B9_22 : 48|16@1+ (1,0) [0|65535] "mv"  PC

BO_ 2336288423 M2P_SUMDATA57__23: 8 MBMU
 SG_ M2P_Power_B9_23 : 0|16@1+ (1,-20000) [-20000|45535] "Kw"  PC
 SG_ M2P_SysremEngy_Chg_B9_23 : 16|16@1+ (1,0) [0|65535] "Kwh"  PC
 SG_ M2P_SysremEngy_DisChg_B9_23 : 32|16@1+ (1,0) [0|65535] "Kwh"  PC
 SG_ M2P_SysMaxVolt_B9_23 : 48|16@1+ (1,0) [0|65535] "mv"  PC

BO_ 2336288424 M2P_SUMDATA57__24: 8 MBMU
 SG_ M2P_Power_B9_24 : 0|16@1+ (1,-20000) [-20000|45535] "Kw"  PC
 SG_ M2P_SysremEngy_Chg_B9_24 : 16|16@1+ (1,0) [0|65535] "Kwh"  PC
 SG_ M2P_SysremEngy_DisChg_B9_24 : 32|16@1+ (1,0) [0|65535] "Kwh"  PC
 SG_ M2P_SysMaxVolt_B9_24 : 48|16@1+ (1,0) [0|65535] "mv"  PC

BO_ 2336288425 M2P_SUMDATA57__25: 8 MBMU
 SG_ M2P_Power_B9_25 : 0|16@1+ (1,-20000) [-20000|45535] "Kw"  PC
 SG_ M2P_SysremEngy_Chg_B9_25 : 16|16@1+ (1,0) [0|65535] "Kwh"  PC
 SG_ M2P_SysremEngy_DisChg_B9_25 : 32|16@1+ (1,0) [0|65535] "Kwh"  PC
 SG_ M2P_SysMaxVolt_B9_25 : 48|16@1+ (1,0) [0|65535] "mv"  PC

BO_ 2336288426 M2P_SUMDATA57__26: 8 MBMU
 SG_ M2P_Power_B9_26 : 0|16@1+ (1,-20000) [-20000|45535] "Kw"  PC
 SG_ M2P_SysremEngy_Chg_B9_26 : 16|16@1+ (1,0) [0|65535] "Kwh"  PC
 SG_ M2P_SysremEngy_DisChg_B9_26 : 32|16@1+ (1,0) [0|65535] "Kwh"  PC
 SG_ M2P_SysMaxVolt_B9_26 : 48|16@1+ (1,0) [0|65535] "mv"  PC

BO_ 2336288427 M2P_SUMDATA57__27: 8 MBMU
 SG_ M2P_Power_B9_27 : 0|16@1+ (1,-20000) [-20000|45535] "Kw"  PC
 SG_ M2P_SysremEngy_Chg_B9_27 : 16|16@1+ (1,0) [0|65535] "Kwh"  PC
 SG_ M2P_SysremEngy_DisChg_B9_27 : 32|16@1+ (1,0) [0|65535] "Kwh"  PC
 SG_ M2P_SysMaxVolt_B9_27 : 48|16@1+ (1,0) [0|65535] "mv"  PC

BO_ 2336288428 M2P_SUMDATA57__28: 8 MBMU
 SG_ M2P_Power_B9_28 : 0|16@1+ (1,-20000) [-20000|45535] "Kw"  PC
 SG_ M2P_SysremEngy_Chg_B9_28 : 16|16@1+ (1,0) [0|65535] "Kwh"  PC
 SG_ M2P_SysremEngy_DisChg_B9_28 : 32|16@1+ (1,0) [0|65535] "Kwh"  PC
 SG_ M2P_SysMaxVolt_B9_28 : 48|16@1+ (1,0) [0|65535] "mv"  PC

BO_ 2336288429 M2P_SUMDATA57__29: 8 MBMU
 SG_ M2P_Power_B9_29 : 0|16@1+ (1,-20000) [-20000|45535] "Kw"  PC
 SG_ M2P_SysremEngy_Chg_B9_29 : 16|16@1+ (1,0) [0|65535] "Kwh"  PC
 SG_ M2P_SysremEngy_DisChg_B9_29 : 32|16@1+ (1,0) [0|65535] "Kwh"  PC
 SG_ M2P_SysMaxVolt_B9_29 : 48|16@1+ (1,0) [0|65535] "mv"  PC

BO_ 2336288430 M2P_SUMDATA57__30: 8 MBMU
 SG_ M2P_Power_B9_30 : 0|16@1+ (1,-20000) [-20000|45535] "Kw"  PC
 SG_ M2P_SysremEngy_Chg_B9_30 : 16|16@1+ (1,0) [0|65535] "Kwh"  PC
 SG_ M2P_SysremEngy_DisChg_B9_30 : 32|16@1+ (1,0) [0|65535] "Kwh"  PC
 SG_ M2P_SysMaxVolt_B9_30 : 48|16@1+ (1,0) [0|65535] "mv"  PC

BO_ 2336288431 M2P_SUMDATA57__31: 8 MBMU
 SG_ M2P_Power_B9_31 : 0|16@1+ (1,-20000) [-20000|45535] "Kw"  PC
 SG_ M2P_SysremEngy_Chg_B9_31 : 16|16@1+ (1,0) [0|65535] "Kwh"  PC
 SG_ M2P_SysremEngy_DisChg_B9_31 : 32|16@1+ (1,0) [0|65535] "Kwh"  PC
 SG_ M2P_SysMaxVolt_B9_31 : 48|16@1+ (1,0) [0|65535] "mv"  PC

BO_ 2336353937 M2P_SUMDATA58__01: 8 MBMU
 SG_ M2P_SysMinVolt_B9_01 : 0|16@1+ (1,0) [0|65535] "mv"  PC
 SG_ M2P_SysAvgVolt_B9_01 : 16|16@1+ (1,0) [0|65535] "mv"  PC
 SG_ M2P_BMS_Status_B9 : 32|3@1+ (1,0) [0|7] ""  PC
 SG_ M2P_SOC_B9 : 35|10@1+ (0.1,0) [0|102.3] "%"  PC
 SG_ M2P_SOH_B9 : 45|8@1+ (1,0) [0|255] "%"  PC
 SG_ Reserved_01 : 53|11@1+ (1,0) [0|2047] ""  PC

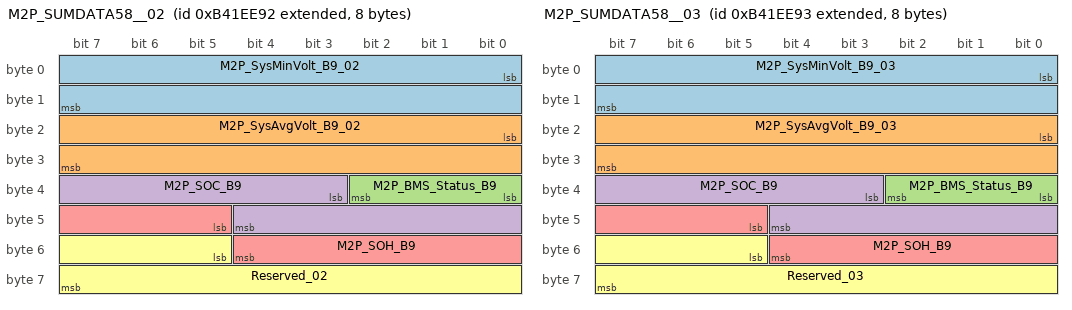
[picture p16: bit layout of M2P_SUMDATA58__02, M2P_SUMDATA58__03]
BO_ 2336353938 M2P_SUMDATA58__02: 8 MBMU
 SG_ M2P_SysMinVolt_B9_02 : 0|16@1+ (1,0) [0|65535] "mv"  PC
 SG_ M2P_SysAvgVolt_B9_02 : 16|16@1+ (1,0) [0|65535] "mv"  PC
 SG_ M2P_BMS_Status_B9 : 32|3@1+ (1,0) [0|7] ""  PC
 SG_ M2P_SOC_B9 : 35|10@1+ (0.1,0) [0|102.3] "%"  PC
 SG_ M2P_SOH_B9 : 45|8@1+ (1,0) [0|255] "%"  PC
 SG_ Reserved_02 : 53|11@1+ (1,0) [0|2047] ""  PC

BO_ 2336353939 M2P_SUMDATA58__03: 8 MBMU
 SG_ M2P_SysMinVolt_B9_03 : 0|16@1+ (1,0) [0|65535] "mv"  PC
 SG_ M2P_SysAvgVolt_B9_03 : 16|16@1+ (1,0) [0|65535] "mv"  PC
 SG_ M2P_BMS_Status_B9 : 32|3@1+ (1,0) [0|7] ""  PC
 SG_ M2P_SOC_B9 : 35|10@1+ (0.1,0) [0|102.3] "%"  PC
 SG_ M2P_SOH_B9 : 45|8@1+ (1,0) [0|255] "%"  PC
 SG_ Reserved_03 : 53|11@1+ (1,0) [0|2047] ""  PC

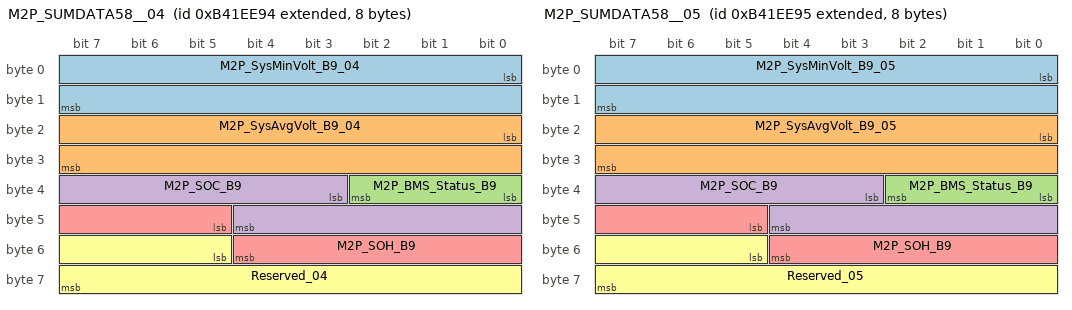
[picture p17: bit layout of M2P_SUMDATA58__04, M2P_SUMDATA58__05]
BO_ 2336353940 M2P_SUMDATA58__04: 8 MBMU
 SG_ M2P_SysMinVolt_B9_04 : 0|16@1+ (1,0) [0|65535] "mv"  PC
 SG_ M2P_SysAvgVolt_B9_04 : 16|16@1+ (1,0) [0|65535] "mv"  PC
 SG_ M2P_BMS_Status_B9 : 32|3@1+ (1,0) [0|7] ""  PC
 SG_ M2P_SOC_B9 : 35|10@1+ (0.1,0) [0|102.3] "%"  PC
 SG_ M2P_SOH_B9 : 45|8@1+ (1,0) [0|255] "%"  PC
 SG_ Reserved_04 : 53|11@1+ (1,0) [0|2047] ""  PC

BO_ 2336353941 M2P_SUMDATA58__05: 8 MBMU
 SG_ M2P_SysMinVolt_B9_05 : 0|16@1+ (1,0) [0|65535] "mv"  PC
 SG_ M2P_SysAvgVolt_B9_05 : 16|16@1+ (1,0) [0|65535] "mv"  PC
 SG_ M2P_BMS_Status_B9 : 32|3@1+ (1,0) [0|7] ""  PC
 SG_ M2P_SOC_B9 : 35|10@1+ (0.1,0) [0|102.3] "%"  PC
 SG_ M2P_SOH_B9 : 45|8@1+ (1,0) [0|255] "%"  PC
 SG_ Reserved_05 : 53|11@1+ (1,0) [0|2047] ""  PC

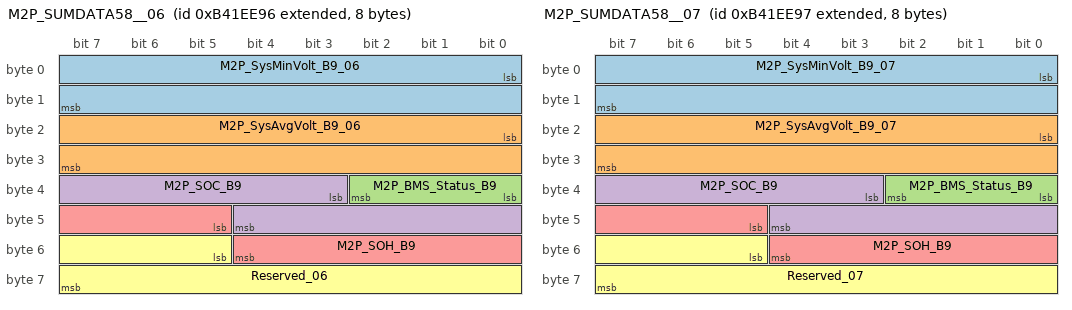
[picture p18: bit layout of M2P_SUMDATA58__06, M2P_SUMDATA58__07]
BO_ 2336353942 M2P_SUMDATA58__06: 8 MBMU
 SG_ M2P_SysMinVolt_B9_06 : 0|16@1+ (1,0) [0|65535] "mv"  PC
 SG_ M2P_SysAvgVolt_B9_06 : 16|16@1+ (1,0) [0|65535] "mv"  PC
 SG_ M2P_BMS_Status_B9 : 32|3@1+ (1,0) [0|7] ""  PC
 SG_ M2P_SOC_B9 : 35|10@1+ (0.1,0) [0|102.3] "%"  PC
 SG_ M2P_SOH_B9 : 45|8@1+ (1,0) [0|255] "%"  PC
 SG_ Reserved_06 : 53|11@1+ (1,0) [0|2047] ""  PC

BO_ 2336353943 M2P_SUMDATA58__07: 8 MBMU
 SG_ M2P_SysMinVolt_B9_07 : 0|16@1+ (1,0) [0|65535] "mv"  PC
 SG_ M2P_SysAvgVolt_B9_07 : 16|16@1+ (1,0) [0|65535] "mv"  PC
 SG_ M2P_BMS_Status_B9 : 32|3@1+ (1,0) [0|7] ""  PC
 SG_ M2P_SOC_B9 : 35|10@1+ (0.1,0) [0|102.3] "%"  PC
 SG_ M2P_SOH_B9 : 45|8@1+ (1,0) [0|255] "%"  PC
 SG_ Reserved_07 : 53|11@1+ (1,0) [0|2047] ""  PC

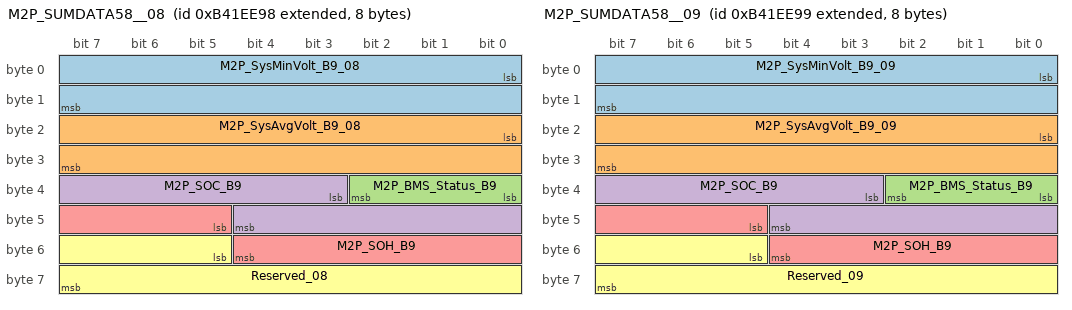
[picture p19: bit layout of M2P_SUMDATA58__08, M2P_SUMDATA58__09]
BO_ 2336353944 M2P_SUMDATA58__08: 8 MBMU
 SG_ M2P_SysMinVolt_B9_08 : 0|16@1+ (1,0) [0|65535] "mv"  PC
 SG_ M2P_SysAvgVolt_B9_08 : 16|16@1+ (1,0) [0|65535] "mv"  PC
 SG_ M2P_BMS_Status_B9 : 32|3@1+ (1,0) [0|7] ""  PC
 SG_ M2P_SOC_B9 : 35|10@1+ (0.1,0) [0|102.3] "%"  PC
 SG_ M2P_SOH_B9 : 45|8@1+ (1,0) [0|255] "%"  PC
 SG_ Reserved_08 : 53|11@1+ (1,0) [0|2047] ""  PC

BO_ 2336353945 M2P_SUMDATA58__09: 8 MBMU
 SG_ M2P_SysMinVolt_B9_09 : 0|16@1+ (1,0) [0|65535] "mv"  PC
 SG_ M2P_SysAvgVolt_B9_09 : 16|16@1+ (1,0) [0|65535] "mv"  PC
 SG_ M2P_BMS_Status_B9 : 32|3@1+ (1,0) [0|7] ""  PC
 SG_ M2P_SOC_B9 : 35|10@1+ (0.1,0) [0|102.3] "%"  PC
 SG_ M2P_SOH_B9 : 45|8@1+ (1,0) [0|255] "%"  PC
 SG_ Reserved_09 : 53|11@1+ (1,0) [0|2047] ""  PC

BO_ 2336353946 M2P_SUMDATA58__10: 8 MBMU
 SG_ M2P_SysMinVolt_B9_10 : 0|16@1+ (1,0) [0|65535] "mv"  PC
 SG_ M2P_SysAvgVolt_B9_10 : 16|16@1+ (1,0) [0|65535] "mv"  PC
 SG_ M2P_BMS_Status_B9 : 32|3@1+ (1,0) [0|7] ""  PC
 SG_ M2P_SOC_B9 : 35|10@1+ (0.1,0) [0|102.3] "%"  PC
 SG_ M2P_SOH_B9 : 45|8@1+ (1,0) [0|255] "%"  PC
 SG_ Reserved_10 : 53|11@1+ (1,0) [0|2047] ""  PC

BO_ 2336353947 M2P_SUMDATA58__11: 8 MBMU
 SG_ M2P_SysMinVolt_B9_11 : 0|16@1+ (1,0) [0|65535] "mv"  PC
 SG_ M2P_SysAvgVolt_B9_11 : 16|16@1+ (1,0) [0|65535] "mv"  PC
 SG_ M2P_BMS_Status_B9 : 32|3@1+ (1,0) [0|7] ""  PC
 SG_ M2P_SOC_B9 : 35|10@1+ (0.1,0) [0|102.3] "%"  PC
 SG_ M2P_SOH_B9 : 45|8@1+ (1,0) [0|255] "%"  PC
 SG_ Reserved_11 : 53|11@1+ (1,0) [0|2047] ""  PC

BO_ 2336353948 M2P_SUMDATA58__12: 8 MBMU
 SG_ M2P_SysMinVolt_B9_12 : 0|16@1+ (1,0) [0|65535] "mv"  PC
 SG_ M2P_SysAvgVolt_B9_12 : 16|16@1+ (1,0) [0|65535] "mv"  PC
 SG_ M2P_BMS_Status_B9 : 32|3@1+ (1,0) [0|7] ""  PC
 SG_ M2P_SOC_B9 : 35|10@1+ (0.1,0) [0|102.3] "%"  PC
 SG_ M2P_SOH_B9 : 45|8@1+ (1,0) [0|255] "%"  PC
 SG_ Reserved_12 : 53|11@1+ (1,0) [0|2047] ""  PC

BO_ 2336353949 M2P_SUMDATA58__13: 8 MBMU
 SG_ M2P_SysMinVolt_B9_13 : 0|16@1+ (1,0) [0|65535] "mv"  PC
 SG_ M2P_SysAvgVolt_B9_13 : 16|16@1+ (1,0) [0|65535] "mv"  PC
 SG_ M2P_BMS_Status_B9 : 32|3@1+ (1,0) [0|7] ""  PC
 SG_ M2P_SOC_B9 : 35|10@1+ (0.1,0) [0|102.3] "%"  PC
 SG_ M2P_SOH_B9 : 45|8@1+ (1,0) [0|255] "%"  PC
 SG_ Reserved_13 : 53|11@1+ (1,0) [0|2047] ""  PC

BO_ 2336353950 M2P_SUMDATA58__14: 8 MBMU
 SG_ M2P_SysMinVolt_B9_14 : 0|16@1+ (1,0) [0|65535] "mv"  PC
 SG_ M2P_SysAvgVolt_B9_14 : 16|16@1+ (1,0) [0|65535] "mv"  PC
 SG_ M2P_BMS_Status_B9 : 32|3@1+ (1,0) [0|7] ""  PC
 SG_ M2P_SOC_B9 : 35|10@1+ (0.1,0) [0|102.3] "%"  PC
 SG_ M2P_SOH_B9 : 45|8@1+ (1,0) [0|255] "%"  PC
 SG_ Reserved_14 : 53|11@1+ (1,0) [0|2047] ""  PC

BO_ 2336353951 M2P_SUMDATA58__15: 8 MBMU
 SG_ M2P_SysMinVolt_B9_15 : 0|16@1+ (1,0) [0|65535] "mv"  PC
 SG_ M2P_SysAvgVolt_B9_15 : 16|16@1+ (1,0) [0|65535] "mv"  PC
 SG_ M2P_BMS_Status_B9 : 32|3@1+ (1,0) [0|7] ""  PC
 SG_ M2P_SOC_B9 : 35|10@1+ (0.1,0) [0|102.3] "%"  PC
 SG_ M2P_SOH_B9 : 45|8@1+ (1,0) [0|255] "%"  PC
 SG_ Reserved_15 : 53|11@1+ (1,0) [0|2047] ""  PC

BO_ 2336353952 M2P_SUMDATA58__16: 8 MBMU
 SG_ M2P_SysMinVolt_B9_16 : 0|16@1+ (1,0) [0|65535] "mv"  PC
 SG_ M2P_SysAvgVolt_B9_16 : 16|16@1+ (1,0) [0|65535] "mv"  PC
 SG_ M2P_BMS_Status_B9 : 32|3@1+ (1,0) [0|7] ""  PC
 SG_ M2P_SOC_B9 : 35|10@1+ (0.1,0) [0|102.3] "%"  PC
 SG_ M2P_SOH_B9 : 45|8@1+ (1,0) [0|255] "%"  PC
 SG_ Reserved_16 : 53|11@1+ (1,0) [0|2047] ""  PC

BO_ 2336353953 M2P_SUMDATA58__17: 8 MBMU
 SG_ M2P_SysMinVolt_B9_17 : 0|16@1+ (1,0) [0|65535] "mv"  PC
 SG_ M2P_SysAvgVolt_B9_17 : 16|16@1+ (1,0) [0|65535] "mv"  PC
 SG_ M2P_BMS_Status_B9 : 32|3@1+ (1,0) [0|7] ""  PC
 SG_ M2P_SOC_B9 : 35|10@1+ (0.1,0) [0|102.3] "%"  PC
 SG_ M2P_SOH_B9 : 45|8@1+ (1,0) [0|255] "%"  PC
 SG_ Reserved_17 : 53|11@1+ (1,0) [0|2047] ""  PC

BO_ 2336353954 M2P_SUMDATA58__18: 8 MBMU
 SG_ M2P_SysMinVolt_B9_18 : 0|16@1+ (1,0) [0|65535] "mv"  PC
 SG_ M2P_SysAvgVolt_B9_18 : 16|16@1+ (1,0) [0|65535] "mv"  PC
 SG_ M2P_BMS_Status_B9 : 32|3@1+ (1,0) [0|7] ""  PC
 SG_ M2P_SOC_B9 : 35|10@1+ (0.1,0) [0|102.3] "%"  PC
 SG_ M2P_SOH_B9 : 45|8@1+ (1,0) [0|255] "%"  PC
 SG_ Reserved_18 : 53|11@1+ (1,0) [0|2047] ""  PC

BO_ 2336353955 M2P_SUMDATA58__19: 8 MBMU
 SG_ M2P_SysMinVolt_B9_19 : 0|16@1+ (1,0) [0|65535] "mv"  PC
 SG_ M2P_SysAvgVolt_B9_19 : 16|16@1+ (1,0) [0|65535] "mv"  PC
 SG_ M2P_BMS_Status_B9 : 32|3@1+ (1,0) [0|7] ""  PC
 SG_ M2P_SOC_B9 : 35|10@1+ (0.1,0) [0|102.3] "%"  PC
 SG_ M2P_SOH_B9 : 45|8@1+ (1,0) [0|255] "%"  PC
 SG_ Reserved_19 : 53|11@1+ (1,0) [0|2047] ""  PC

BO_ 2336353956 M2P_SUMDATA58__20: 8 MBMU
 SG_ M2P_SysMinVolt_B9_20 : 0|16@1+ (1,0) [0|65535] "mv"  PC
 SG_ M2P_SysAvgVolt_B9_20 : 16|16@1+ (1,0) [0|65535] "mv"  PC
 SG_ M2P_BMS_Status_B9 : 32|3@1+ (1,0) [0|7] ""  PC
 SG_ M2P_SOC_B9 : 35|10@1+ (0.1,0) [0|102.3] "%"  PC
 SG_ M2P_SOH_B9 : 45|8@1+ (1,0) [0|255] "%"  PC
 SG_ Reserved_20 : 53|11@1+ (1,0) [0|2047] ""  PC

BO_ 2336353957 M2P_SUMDATA58__21: 8 MBMU
 SG_ M2P_SysMinVolt_B9_21 : 0|16@1+ (1,0) [0|65535] "mv"  PC
 SG_ M2P_SysAvgVolt_B9_21 : 16|16@1+ (1,0) [0|65535] "mv"  PC
 SG_ M2P_BMS_Status_B9 : 32|3@1+ (1,0) [0|7] ""  PC
 SG_ M2P_SOC_B9 : 35|10@1+ (0.1,0) [0|102.3] "%"  PC
 SG_ M2P_SOH_B9 : 45|8@1+ (1,0) [0|255] "%"  PC
 SG_ Reserved_21 : 53|11@1+ (1,0) [0|2047] ""  PC

BO_ 2336353958 M2P_SUMDATA58__22: 8 MBMU
 SG_ M2P_SysMinVolt_B9_22 : 0|16@1+ (1,0) [0|65535] "mv"  PC
 SG_ M2P_SysAvgVolt_B9_22 : 16|16@1+ (1,0) [0|65535] "mv"  PC
 SG_ M2P_BMS_Status_B9 : 32|3@1+ (1,0) [0|7] ""  PC
 SG_ M2P_SOC_B9 : 35|10@1+ (0.1,0) [0|102.3] "%"  PC
 SG_ M2P_SOH_B9 : 45|8@1+ (1,0) [0|255] "%"  PC
 SG_ Reserved_22 : 53|11@1+ (1,0) [0|2047] ""  PC

BO_ 2336353959 M2P_SUMDATA58__23: 8 MBMU
 SG_ M2P_SysMinVolt_B9_23 : 0|16@1+ (1,0) [0|65535] "mv"  PC
 SG_ M2P_SysAvgVolt_B9_23 : 16|16@1+ (1,0) [0|65535] "mv"  PC
 SG_ M2P_BMS_Status_B9 : 32|3@1+ (1,0) [0|7] ""  PC
 SG_ M2P_SOC_B9 : 35|10@1+ (0.1,0) [0|102.3] "%"  PC
 SG_ M2P_SOH_B9 : 45|8@1+ (1,0) [0|255] "%"  PC
 SG_ Reserved_23 : 53|11@1+ (1,0) [0|2047] ""  PC

BO_ 2336353960 M2P_SUMDATA58__24: 8 MBMU
 SG_ M2P_SysMinVolt_B9_24 : 0|16@1+ (1,0) [0|65535] "mv"  PC
 SG_ M2P_SysAvgVolt_B9_24 : 16|16@1+ (1,0) [0|65535] "mv"  PC
 SG_ M2P_BMS_Status_B9 : 32|3@1+ (1,0) [0|7] ""  PC
 SG_ M2P_SOC_B9 : 35|10@1+ (0.1,0) [0|102.3] "%"  PC
 SG_ M2P_SOH_B9 : 45|8@1+ (1,0) [0|255] "%"  PC
 SG_ Reserved_24 : 53|11@1+ (1,0) [0|2047] ""  PC

BO_ 2336353961 M2P_SUMDATA58__25: 8 MBMU
 SG_ M2P_SysMinVolt_B9_25 : 0|16@1+ (1,0) [0|65535] "mv"  PC
 SG_ M2P_SysAvgVolt_B9_25 : 16|16@1+ (1,0) [0|65535] "mv"  PC
 SG_ M2P_BMS_Status_B9 : 32|3@1+ (1,0) [0|7] ""  PC
 SG_ M2P_SOC_B9 : 35|10@1+ (0.1,0) [0|102.3] "%"  PC
 SG_ M2P_SOH_B9 : 45|8@1+ (1,0) [0|255] "%"  PC
 SG_ Reserved_25 : 53|11@1+ (1,0) [0|2047] ""  PC

BO_ 2336353962 M2P_SUMDATA58__26: 8 MBMU
 SG_ M2P_SysMinVolt_B9_26 : 0|16@1+ (1,0) [0|65535] "mv"  PC
 SG_ M2P_SysAvgVolt_B9_26 : 16|16@1+ (1,0) [0|65535] "mv"  PC
 SG_ M2P_BMS_Status_B9 : 32|3@1+ (1,0) [0|7] ""  PC
 SG_ M2P_SOC_B9 : 35|10@1+ (0.1,0) [0|102.3] "%"  PC
 SG_ M2P_SOH_B9 : 45|8@1+ (1,0) [0|255] "%"  PC
 SG_ Reserved_26 : 53|11@1+ (1,0) [0|2047] ""  PC

BO_ 2336353963 M2P_SUMDATA58__27: 8 MBMU
 SG_ M2P_SysMinVolt_B9_27 : 0|16@1+ (1,0) [0|65535] "mv"  PC
 SG_ M2P_SysAvgVolt_B9_27 : 16|16@1+ (1,0) [0|65535] "mv"  PC
 SG_ M2P_BMS_Status_B9 : 32|3@1+ (1,0) [0|7] ""  PC
 SG_ M2P_SOC_B9 : 35|10@1+ (0.1,0) [0|102.3] "%"  PC
 SG_ M2P_SOH_B9 : 45|8@1+ (1,0) [0|255] "%"  PC
 SG_ Reserved_27 : 53|11@1+ (1,0) [0|2047] ""  PC

BO_ 2336353964 M2P_SUMDATA58__28: 8 MBMU
 SG_ M2P_SysMinVolt_B9_28 : 0|16@1+ (1,0) [0|65535] "mv"  PC
 SG_ M2P_SysAvgVolt_B9_28 : 16|16@1+ (1,0) [0|65535] "mv"  PC
 SG_ M2P_BMS_Status_B9 : 32|3@1+ (1,0) [0|7] ""  PC
 SG_ M2P_SOC_B9 : 35|10@1+ (0.1,0) [0|102.3] "%"  PC
 SG_ M2P_SOH_B9 : 45|8@1+ (1,0) [0|255] "%"  PC
 SG_ Reserved_28 : 53|11@1+ (1,0) [0|2047] ""  PC

BO_ 2336353965 M2P_SUMDATA58__29: 8 MBMU
 SG_ M2P_SysMinVolt_B9_29 : 0|16@1+ (1,0) [0|65535] "mv"  PC
 SG_ M2P_SysAvgVolt_B9_29 : 16|16@1+ (1,0) [0|65535] "mv"  PC
 SG_ M2P_BMS_Status_B9 : 32|3@1+ (1,0) [0|7] ""  PC
 SG_ M2P_SOC_B9 : 35|10@1+ (0.1,0) [0|102.3] "%"  PC
 SG_ M2P_SOH_B9 : 45|8@1+ (1,0) [0|255] "%"  PC
 SG_ Reserved_29 : 53|11@1+ (1,0) [0|2047] ""  PC

BO_ 2336353966 M2P_SUMDATA58__30: 8 MBMU
 SG_ M2P_SysMinVolt_B9_30 : 0|16@1+ (1,0) [0|65535] "mv"  PC
 SG_ M2P_SysAvgVolt_B9_30 : 16|16@1+ (1,0) [0|65535] "mv"  PC
 SG_ M2P_BMS_Status_B9 : 32|3@1+ (1,0) [0|7] ""  PC
 SG_ M2P_SOC_B9 : 35|10@1+ (0.1,0) [0|102.3] "%"  PC
 SG_ M2P_SOH_B9 : 45|8@1+ (1,0) [0|255] "%"  PC
 SG_ Reserved_30 : 53|11@1+ (1,0) [0|2047] ""  PC

BO_ 2336353967 M2P_SUMDATA58__31: 8 MBMU
 SG_ M2P_SysMinVolt_B9_31 : 0|16@1+ (1,0) [0|65535] "mv"  PC
 SG_ M2P_SysAvgVolt_B9_31 : 16|16@1+ (1,0) [0|65535] "mv"  PC
 SG_ M2P_BMS_Status_B9 : 32|3@1+ (1,0) [0|7] ""  PC
 SG_ M2P_SOC_B9 : 35|10@1+ (0.1,0) [0|102.3] "%"  PC
 SG_ M2P_SOH_B9 : 45|8@1+ (1,0) [0|255] "%"  PC
 SG_ Reserved_31 : 53|11@1+ (1,0) [0|2047] ""  PC

BO_ 2336419473 M2P_SUMDATA59__01: 8 MBMU
 SG_ M2P_SOE_Charge_B9 : 0|10@1+ (0.1,0) [0|102.3] "%"  PC
 SG_ M2P_SOE_Discharge_B9 : 10|10@1+ (0.1,0) [0|102.3] "%"  PC
 SG_ Reserved_01 : 20|44@1+ (1,0) [0|17592186044415] ""  PC

BO_ 2336419474 M2P_SUMDATA59__02: 8 MBMU
 SG_ M2P_SOE_Charge_B9 : 0|10@1+ (0.1,0) [0|102.3] "%"  PC
 SG_ M2P_SOE_Discharge_B9 : 10|10@1+ (0.1,0) [0|102.3] "%"  PC
 SG_ Reserved_02 : 20|44@1+ (1,0) [0|17592186044415] ""  PC

BO_ 2336419475 M2P_SUMDATA59__03: 8 MBMU
 SG_ M2P_SOE_Charge_B9 : 0|10@1+ (0.1,0) [0|102.3] "%"  PC
 SG_ M2P_SOE_Discharge_B9 : 10|10@1+ (0.1,0) [0|102.3] "%"  PC
 SG_ Reserved_03 : 20|44@1+ (1,0) [0|17592186044415] ""  PC

BO_ 2336419476 M2P_SUMDATA59__04: 8 MBMU
 SG_ M2P_SOE_Charge_B9 : 0|10@1+ (0.1,0) [0|102.3] "%"  PC
 SG_ M2P_SOE_Discharge_B9 : 10|10@1+ (0.1,0) [0|102.3] "%"  PC
 SG_ Reserved_04 : 20|44@1+ (1,0) [0|17592186044415] ""  PC

BO_ 2336419477 M2P_SUMDATA59__05: 8 MBMU
 SG_ M2P_SOE_Charge_B9 : 0|10@1+ (0.1,0) [0|102.3] "%"  PC
 SG_ M2P_SOE_Discharge_B9 : 10|10@1+ (0.1,0) [0|102.3] "%"  PC
 SG_ Reserved_05 : 20|44@1+ (1,0) [0|17592186044415] ""  PC

BO_ 2336419478 M2P_SUMDATA59__06: 8 MBMU
 SG_ M2P_SOE_Charge_B9 : 0|10@1+ (0.1,0) [0|102.3] "%"  PC
 SG_ M2P_SOE_Discharge_B9 : 10|10@1+ (0.1,0) [0|102.3] "%"  PC
 SG_ Reserved_06 : 20|44@1+ (1,0) [0|17592186044415] ""  PC

BO_ 2336419479 M2P_SUMDATA59__07: 8 MBMU
 SG_ M2P_SOE_Charge_B9 : 0|10@1+ (0.1,0) [0|102.3] "%"  PC
 SG_ M2P_SOE_Discharge_B9 : 10|10@1+ (0.1,0) [0|102.3] "%"  PC
 SG_ Reserved_07 : 20|44@1+ (1,0) [0|17592186044415] ""  PC

BO_ 2336419480 M2P_SUMDATA59__08: 8 MBMU
 SG_ M2P_SOE_Charge_B9 : 0|10@1+ (0.1,0) [0|102.3] "%"  PC
 SG_ M2P_SOE_Discharge_B9 : 10|10@1+ (0.1,0) [0|102.3] "%"  PC
 SG_ Reserved_08 : 20|44@1+ (1,0) [0|17592186044415] ""  PC

BO_ 2336419481 M2P_SUMDATA59__09: 8 MBMU
 SG_ M2P_SOE_Charge_B9 : 0|10@1+ (0.1,0) [0|102.3] "%"  PC
 SG_ M2P_SOE_Discharge_B9 : 10|10@1+ (0.1,0) [0|102.3] "%"  PC
 SG_ Reserved_09 : 20|44@1+ (1,0) [0|17592186044415] ""  PC

BO_ 2336419482 M2P_SUMDATA59__10: 8 MBMU
 SG_ M2P_SOE_Charge_B9 : 0|10@1+ (0.1,0) [0|102.3] "%"  PC
 SG_ M2P_SOE_Discharge_B9 : 10|10@1+ (0.1,0) [0|102.3] "%"  PC
 SG_ Reserved_10 : 20|44@1+ (1,0) [0|17592186044415] ""  PC

BO_ 2336419483 M2P_SUMDATA59__11: 8 MBMU
 SG_ M2P_SOE_Charge_B9 : 0|10@1+ (0.1,0) [0|102.3] "%"  PC
 SG_ M2P_SOE_Discharge_B9 : 10|10@1+ (0.1,0) [0|102.3] "%"  PC
 SG_ Reserved_11 : 20|44@1+ (1,0) [0|17592186044415] ""  PC

BO_ 2336419484 M2P_SUMDATA59__12: 8 MBMU
 SG_ M2P_SOE_Charge_B9 : 0|10@1+ (0.1,0) [0|102.3] "%"  PC
 SG_ M2P_SOE_Discharge_B9 : 10|10@1+ (0.1,0) [0|102.3] "%"  PC
 SG_ Reserved_12 : 20|44@1+ (1,0) [0|17592186044415] ""  PC

BO_ 2336419485 M2P_SUMDATA59__13: 8 MBMU
 SG_ M2P_SOE_Charge_B9 : 0|10@1+ (0.1,0) [0|102.3] "%"  PC
 SG_ M2P_SOE_Discharge_B9 : 10|10@1+ (0.1,0) [0|102.3] "%"  PC
 SG_ Reserved_13 : 20|44@1+ (1,0) [0|17592186044415] ""  PC

BO_ 2336419486 M2P_SUMDATA59__14: 8 MBMU
 SG_ M2P_SOE_Charge_B9 : 0|10@1+ (0.1,0) [0|102.3] "%"  PC
 SG_ M2P_SOE_Discharge_B9 : 10|10@1+ (0.1,0) [0|102.3] "%"  PC
 SG_ Reserved_14 : 20|44@1+ (1,0) [0|17592186044415] ""  PC

BO_ 2336419487 M2P_SUMDATA59__15: 8 MBMU
 SG_ M2P_SOE_Charge_B9 : 0|10@1+ (0.1,0) [0|102.3] "%"  PC
 SG_ M2P_SOE_Discharge_B9 : 10|10@1+ (0.1,0) [0|102.3] "%"  PC
 SG_ Reserved_15 : 20|44@1+ (1,0) [0|17592186044415] ""  PC

BO_ 2336419488 M2P_SUMDATA59__16: 8 MBMU
 SG_ M2P_SOE_Charge_B9 : 0|10@1+ (0.1,0) [0|102.3] "%"  PC
 SG_ M2P_SOE_Discharge_B9 : 10|10@1+ (0.1,0) [0|102.3] "%"  PC
 SG_ Reserved_16 : 20|44@1+ (1,0) [0|17592186044415] ""  PC

BO_ 2336419489 M2P_SUMDATA59__17: 8 MBMU
 SG_ M2P_SOE_Charge_B9 : 0|10@1+ (0.1,0) [0|102.3] "%"  PC
 SG_ M2P_SOE_Discharge_B9 : 10|10@1+ (0.1,0) [0|102.3] "%"  PC
 SG_ Reserved_17 : 20|44@1+ (1,0) [0|17592186044415] ""  PC

BO_ 2336419490 M2P_SUMDATA59__18: 8 MBMU
 SG_ M2P_SOE_Charge_B9 : 0|10@1+ (0.1,0) [0|102.3] "%"  PC
 SG_ M2P_SOE_Discharge_B9 : 10|10@1+ (0.1,0) [0|102.3] "%"  PC
 SG_ Reserved_18 : 20|44@1+ (1,0) [0|17592186044415] ""  PC

BO_ 2336419491 M2P_SUMDATA59__19: 8 MBMU
 SG_ M2P_SOE_Charge_B9 : 0|10@1+ (0.1,0) [0|102.3] "%"  PC
 SG_ M2P_SOE_Discharge_B9 : 10|10@1+ (0.1,0) [0|102.3] "%"  PC
 SG_ Reserved_19 : 20|44@1+ (1,0) [0|17592186044415] ""  PC

BO_ 2336419492 M2P_SUMDATA59__20: 8 MBMU
 SG_ M2P_SOE_Charge_B9 : 0|10@1+ (0.1,0) [0|102.3] "%"  PC
 SG_ M2P_SOE_Discharge_B9 : 10|10@1+ (0.1,0) [0|102.3] "%"  PC
 SG_ Reserved_20 : 20|44@1+ (1,0) [0|17592186044415] ""  PC

BO_ 2336419493 M2P_SUMDATA59__21: 8 MBMU
 SG_ M2P_SOE_Charge_B9 : 0|10@1+ (0.1,0) [0|102.3] "%"  PC
 SG_ M2P_SOE_Discharge_B9 : 10|10@1+ (0.1,0) [0|102.3] "%"  PC
 SG_ Reserved_21 : 20|44@1+ (1,0) [0|17592186044415] ""  PC

BO_ 2336419494 M2P_SUMDATA59__22: 8 MBMU
 SG_ M2P_SOE_Charge_B9 : 0|10@1+ (0.1,0) [0|102.3] "%"  PC
 SG_ M2P_SOE_Discharge_B9 : 10|10@1+ (0.1,0) [0|102.3] "%"  PC
 SG_ Reserved_22 : 20|44@1+ (1,0) [0|17592186044415] ""  PC

BO_ 2336419495 M2P_SUMDATA59__23: 8 MBMU
 SG_ M2P_SOE_Charge_B9 : 0|10@1+ (0.1,0) [0|102.3] "%"  PC
 SG_ M2P_SOE_Discharge_B9 : 10|10@1+ (0.1,0) [0|102.3] "%"  PC
 SG_ Reserved_23 : 20|44@1+ (1,0) [0|17592186044415] ""  PC

BO_ 2336419496 M2P_SUMDATA59__24: 8 MBMU
 SG_ M2P_SOE_Charge_B9 : 0|10@1+ (0.1,0) [0|102.3] "%"  PC
 SG_ M2P_SOE_Discharge_B9 : 10|10@1+ (0.1,0) [0|102.3] "%"  PC
 SG_ Reserved_24 : 20|44@1+ (1,0) [0|17592186044415] ""  PC

BO_ 2336419497 M2P_SUMDATA59__25: 8 MBMU
 SG_ M2P_SOE_Charge_B9 : 0|10@1+ (0.1,0) [0|102.3] "%"  PC
 SG_ M2P_SOE_Discharge_B9 : 10|10@1+ (0.1,0) [0|102.3] "%"  PC
 SG_ Reserved_25 : 20|44@1+ (1,0) [0|17592186044415] ""  PC

BO_ 2336419498 M2P_SUMDATA59__26: 8 MBMU
 SG_ M2P_SOE_Charge_B9 : 0|10@1+ (0.1,0) [0|102.3] "%"  PC
 SG_ M2P_SOE_Discharge_B9 : 10|10@1+ (0.1,0) [0|102.3] "%"  PC
 SG_ Reserved_26 : 20|44@1+ (1,0) [0|17592186044415] ""  PC

BO_ 2336419499 M2P_SUMDATA59__27: 8 MBMU
 SG_ M2P_SOE_Charge_B9 : 0|10@1+ (0.1,0) [0|102.3] "%"  PC
 SG_ M2P_SOE_Discharge_B9 : 10|10@1+ (0.1,0) [0|102.3] "%"  PC
 SG_ Reserved_27 : 20|44@1+ (1,0) [0|17592186044415] ""  PC

BO_ 2336419500 M2P_SUMDATA59__28: 8 MBMU
 SG_ M2P_SOE_Charge_B9 : 0|10@1+ (0.1,0) [0|102.3] "%"  PC
 SG_ M2P_SOE_Discharge_B9 : 10|10@1+ (0.1,0) [0|102.3] "%"  PC
 SG_ Reserved_28 : 20|44@1+ (1,0) [0|17592186044415] ""  PC

BO_ 2336419501 M2P_SUMDATA59__29: 8 MBMU
 SG_ M2P_SOE_Charge_B9 : 0|10@1+ (0.1,0) [0|102.3] "%"  PC
 SG_ M2P_SOE_Discharge_B9 : 10|10@1+ (0.1,0) [0|102.3] "%"  PC
 SG_ Reserved_29 : 20|44@1+ (1,0) [0|17592186044415] ""  PC

BO_ 2336419502 M2P_SUMDATA59__30: 8 MBMU
 SG_ M2P_SOE_Charge_B9 : 0|10@1+ (0.1,0) [0|102.3] "%"  PC
 SG_ M2P_SOE_Discharge_B9 : 10|10@1+ (0.1,0) [0|102.3] "%"  PC
 SG_ Reserved_30 : 20|44@1+ (1,0) [0|17592186044415] ""  PC

BO_ 2336419503 M2P_SUMDATA59__31: 8 MBMU
 SG_ M2P_SOE_Charge_B9 : 0|10@1+ (0.1,0) [0|102.3] "%"  PC
 SG_ M2P_SOE_Discharge_B9 : 10|10@1+ (0.1,0) [0|102.3] "%"  PC
 SG_ Reserved_31 : 20|44@1+ (1,0) [0|17592186044415] ""  PC

BO_ 2336485009 M2P_SUMDATA60__01: 8 MBMU
 SG_ M2P_Measure_Vol_B10_01 : 0|16@1+ (0.1,0) [0|6553.5] "V"  PC,SBMU
 SG_ M2P_Current_B10_01 : 16|16@1+ (1,-20000) [-20000|45535] "A"  PC,SBMU
 SG_ M2P_PermitMaxCharge_I_B10_01 : 32|16@1+ (1,-20000) [-20000|45535] "A"  PC
 SG_ M2P_PermitMaxDisCharge_I_B10_01 : 48|16@1+ (1,-20000) [-20000|45535] "A"  PC

BO_ 2336485010 M2P_SUMDATA60__02: 8 MBMU
 SG_ M2P_Measure_Vol_B10_02 : 0|16@1+ (0.1,0) [0|6553.5] "V"  PC,SBMU
 SG_ M2P_Current_B10_02 : 16|16@1+ (1,-20000) [-20000|45535] "A"  PC,SBMU
 SG_ M2P_PermitMaxCharge_I_B10_02 : 32|16@1+ (1,-20000) [-20000|45535] "A"  PC
 SG_ M2P_PermitMaxDisCharge_I_B10_02 : 48|16@1+ (1,-20000) [-20000|45535] "A"  PC

BO_ 2336485011 M2P_SUMDATA60__03: 8 MBMU
 SG_ M2P_Measure_Vol_B10_03 : 0|16@1+ (0.1,0) [0|6553.5] "V"  PC,SBMU
 SG_ M2P_Current_B10_03 : 16|16@1+ (1,-20000) [-20000|45535] "A"  PC,SBMU
 SG_ M2P_PermitMaxCharge_I_B10_03 : 32|16@1+ (1,-20000) [-20000|45535] "A"  PC
 SG_ M2P_PermitMaxDisCharge_I_B10_03 : 48|16@1+ (1,-20000) [-20000|45535] "A"  PC

BO_ 2336485012 M2P_SUMDATA60__04: 8 MBMU
 SG_ M2P_Measure_Vol_B10_04 : 0|16@1+ (0.1,0) [0|6553.5] "V"  PC,SBMU
 SG_ M2P_Current_B10_04 : 16|16@1+ (1,-20000) [-20000|45535] "A"  PC,SBMU
 SG_ M2P_PermitMaxCharge_I_B10_04 : 32|16@1+ (1,-20000) [-20000|45535] "A"  PC
 SG_ M2P_PermitMaxDisCharge_I_B10_04 : 48|16@1+ (1,-20000) [-20000|45535] "A"  PC

BO_ 2336485013 M2P_SUMDATA60__05: 8 MBMU
 SG_ M2P_Measure_Vol_B10_05 : 0|16@1+ (0.1,0) [0|6553.5] "V"  PC,SBMU
 SG_ M2P_Current_B10_05 : 16|16@1+ (1,-20000) [-20000|45535] "A"  PC,SBMU
 SG_ M2P_PermitMaxCharge_I_B10_05 : 32|16@1+ (1,-20000) [-20000|45535] "A"  PC
 SG_ M2P_PermitMaxDisCharge_I_B10_05 : 48|16@1+ (1,-20000) [-20000|45535] "A"  PC

BO_ 2336485014 M2P_SUMDATA60__06: 8 MBMU
 SG_ M2P_Measure_Vol_B10_06 : 0|16@1+ (0.1,0) [0|6553.5] "V"  PC,SBMU
 SG_ M2P_Current_B10_06 : 16|16@1+ (1,-20000) [-20000|45535] "A"  PC,SBMU
 SG_ M2P_PermitMaxCharge_I_B10_06 : 32|16@1+ (1,-20000) [-20000|45535] "A"  PC
 SG_ M2P_PermitMaxDisCharge_I_B10_06 : 48|16@1+ (1,-20000) [-20000|45535] "A"  PC

BO_ 2336485015 M2P_SUMDATA60__07: 8 MBMU
 SG_ M2P_Measure_Vol_B10_07 : 0|16@1+ (0.1,0) [0|6553.5] "V"  PC,SBMU
 SG_ M2P_Current_B10_07 : 16|16@1+ (1,-20000) [-20000|45535] "A"  PC,SBMU
 SG_ M2P_PermitMaxCharge_I_B10_07 : 32|16@1+ (1,-20000) [-20000|45535] "A"  PC
 SG_ M2P_PermitMaxDisCharge_I_B10_07 : 48|16@1+ (1,-20000) [-20000|45535] "A"  PC

BO_ 2336485016 M2P_SUMDATA60__08: 8 MBMU
 SG_ M2P_Measure_Vol_B10_08 : 0|16@1+ (0.1,0) [0|6553.5] "V"  PC,SBMU
 SG_ M2P_Current_B10_08 : 16|16@1+ (1,-20000) [-20000|45535] "A"  PC,SBMU
 SG_ M2P_PermitMaxCharge_I_B10_08 : 32|16@1+ (1,-20000) [-20000|45535] "A"  PC
 SG_ M2P_PermitMaxDisCharge_I_B10_08 : 48|16@1+ (1,-20000) [-20000|45535] "A"  PC

BO_ 2336485017 M2P_SUMDATA60__09: 8 MBMU
 SG_ M2P_Measure_Vol_B10_09 : 0|16@1+ (0.1,0) [0|6553.5] "V"  PC,SBMU
 SG_ M2P_Current_B10_09 : 16|16@1+ (1,-20000) [-20000|45535] "A"  PC,SBMU
 SG_ M2P_PermitMaxCharge_I_B10_09 : 32|16@1+ (1,-20000) [-20000|45535] "A"  PC
 SG_ M2P_PermitMaxDisCharge_I_B10_09 : 48|16@1+ (1,-20000) [-20000|45535] "A"  PC

BO_ 2336485018 M2P_SUMDATA60__10: 8 MBMU
 SG_ M2P_Measure_Vol_B10_10 : 0|16@1+ (0.1,0) [0|6553.5] "V"  PC,SBMU
 SG_ M2P_Current_B10_10 : 16|16@1+ (1,-20000) [-20000|45535] "A"  PC,SBMU
 SG_ M2P_PermitMaxCharge_I_B10_10 : 32|16@1+ (1,-20000) [-20000|45535] "A"  PC
 SG_ M2P_PermitMaxDisCharge_I_B10_10 : 48|16@1+ (1,-20000) [-20000|45535] "A"  PC

BO_ 2336485019 M2P_SUMDATA60__11: 8 MBMU
 SG_ M2P_Measure_Vol_B10_11 : 0|16@1+ (0.1,0) [0|6553.5] "V"  PC,SBMU
 SG_ M2P_Current_B10_11 : 16|16@1+ (1,-20000) [-20000|45535] "A"  PC,SBMU
 SG_ M2P_PermitMaxCharge_I_B10_11 : 32|16@1+ (1,-20000) [-20000|45535] "A"  PC
 SG_ M2P_PermitMaxDisCharge_I_B10_11 : 48|16@1+ (1,-20000) [-20000|45535] "A"  PC

BO_ 2336485020 M2P_SUMDATA60__12: 8 MBMU
 SG_ M2P_Measure_Vol_B10_12 : 0|16@1+ (0.1,0) [0|6553.5] "V"  PC,SBMU
 SG_ M2P_Current_B10_12 : 16|16@1+ (1,-20000) [-20000|45535] "A"  PC,SBMU
 SG_ M2P_PermitMaxCharge_I_B10_12 : 32|16@1+ (1,-20000) [-20000|45535] "A"  PC
 SG_ M2P_PermitMaxDisCharge_I_B10_12 : 48|16@1+ (1,-20000) [-20000|45535] "A"  PC

BO_ 2336485021 M2P_SUMDATA60__13: 8 MBMU
 SG_ M2P_Measure_Vol_B10_13 : 0|16@1+ (0.1,0) [0|6553.5] "V"  PC,SBMU
 SG_ M2P_Current_B10_13 : 16|16@1+ (1,-20000) [-20000|45535] "A"  PC,SBMU
 SG_ M2P_PermitMaxCharge_I_B10_13 : 32|16@1+ (1,-20000) [-20000|45535] "A"  PC
 SG_ M2P_PermitMaxDisCharge_I_B10_13 : 48|16@1+ (1,-20000) [-20000|45535] "A"  PC

BO_ 2336485022 M2P_SUMDATA60__14: 8 MBMU
 SG_ M2P_Measure_Vol_B10_14 : 0|16@1+ (0.1,0) [0|6553.5] "V"  PC,SBMU
 SG_ M2P_Current_B10_14 : 16|16@1+ (1,-20000) [-20000|45535] "A"  PC,SBMU
 SG_ M2P_PermitMaxCharge_I_B10_14 : 32|16@1+ (1,-20000) [-20000|45535] "A"  PC
 SG_ M2P_PermitMaxDisCharge_I_B10_14 : 48|16@1+ (1,-20000) [-20000|45535] "A"  PC

BO_ 2336485023 M2P_SUMDATA60__15: 8 MBMU
 SG_ M2P_Measure_Vol_B10_15 : 0|16@1+ (0.1,0) [0|6553.5] "V"  PC,SBMU
 SG_ M2P_Current_B10_15 : 16|16@1+ (1,-20000) [-20000|45535] "A"  PC,SBMU
 SG_ M2P_PermitMaxCharge_I_B10_15 : 32|16@1+ (1,-20000) [-20000|45535] "A"  PC
 SG_ M2P_PermitMaxDisCharge_I_B10_15 : 48|16@1+ (1,-20000) [-20000|45535] "A"  PC

CM_ SG_ 2335895201 M2P_PermitMaxVolt_B8_17 "汇流排8最高允许充电电压 （配置量）";
CM_ SG_ 2335895201 M2P_PermitMinVolt_B8_17 "汇流排8最低允许放电电压 （配置量）";
CM_ SG_ 2335895201 M2P_PermitMaxPow_Chg_B8_17 "汇流排8最大允许充电功率";
CM_ SG_ 2335895201 M2P_PermitMaxPow_DisChg_B8_17 "汇流排8最大允许放电功率";
CM_ SG_ 2335895202 M2P_PermitMaxVolt_B8_18 "汇流排8最高允许充电电压 （配置量）";
CM_ SG_ 2335895202 M2P_PermitMinVolt_B8_18 "汇流排8最低允许放电电压 （配置量）";
CM_ SG_ 2335895202 M2P_PermitMaxPow_Chg_B8_18 "汇流排8最大允许充电功率";
CM_ SG_ 2335895202 M2P_PermitMaxPow_DisChg_B8_18 "汇流排8最大允许放电功率";
CM_ SG_ 2335895203 M2P_PermitMaxVolt_B8_19 "汇流排8最高允许充电电压 （配置量）";
CM_ SG_ 2335895203 M2P_PermitMinVolt_B8_19 "汇流排8最低允许放电电压 （配置量）";
CM_ SG_ 2335895203 M2P_PermitMaxPow_Chg_B8_19 "汇流排8最大允许充电功率";
CM_ SG_ 2335895203 M2P_PermitMaxPow_DisChg_B8_19 "汇流排8最大允许放电功率";
CM_ SG_ 2335895204 M2P_PermitMaxVolt_B8_20 "汇流排8最高允许充电电压 （配置量）";
CM_ SG_ 2335895204 M2P_PermitMinVolt_B8_20 "汇流排8最低允许放电电压 （配置量）";
CM_ SG_ 2335895204 M2P_PermitMaxPow_Chg_B8_20 "汇流排8最大允许充电功率";
CM_ SG_ 2335895204 M2P_PermitMaxPow_DisChg_B8_20 "汇流排8最大允许放电功率";
CM_ SG_ 2335895205 M2P_PermitMaxVolt_B8_21 "汇流排8最高允许充电电压 （配置量）";
CM_ SG_ 2335895205 M2P_PermitMinVolt_B8_21 "汇流排8最低允许放电电压 （配置量）";
CM_ SG_ 2335895205 M2P_PermitMaxPow_Chg_B8_21 "汇流排8最大允许充电功率";
CM_ SG_ 2335895205 M2P_PermitMaxPow_DisChg_B8_21 "汇流排8最大允许放电功率";
CM_ SG_ 2335895206 M2P_PermitMaxVolt_B8_22 "汇流排8最高允许充电电压 （配置量）";
CM_ SG_ 2335895206 M2P_PermitMinVolt_B8_22 "汇流排8最低允许放电电压 （配置量）";
CM_ SG_ 2335895206 M2P_PermitMaxPow_Chg_B8_22 "汇流排8最大允许充电功率";
CM_ SG_ 2335895206 M2P_PermitMaxPow_DisChg_B8_22 "汇流排8最大允许放电功率";
CM_ SG_ 2335895207 M2P_PermitMaxVolt_B8_23 "汇流排8最高允许充电电压 （配置量）";
CM_ SG_ 2335895207 M2P_PermitMinVolt_B8_23 "汇流排8最低允许放电电压 （配置量）";
CM_ SG_ 2335895207 M2P_PermitMaxPow_Chg_B8_23 "汇流排8最大允许充电功率";
CM_ SG_ 2335895207 M2P_PermitMaxPow_DisChg_B8_23 "汇流排8最大允许放电功率";
CM_ SG_ 2335895208 M2P_PermitMaxVolt_B8_24 "汇流排8最高允许充电电压 （配置量）";
CM_ SG_ 2335895208 M2P_PermitMinVolt_B8_24 "汇流排8最低允许放电电压 （配置量）";
CM_ SG_ 2335895208 M2P_PermitMaxPow_Chg_B8_24 "汇流排8最大允许充电功率";
CM_ SG_ 2335895208 M2P_PermitMaxPow_DisChg_B8_24 "汇流排8最大允许放电功率";
CM_ SG_ 2335895209 M2P_PermitMaxVolt_B8_25 "汇流排8最高允许充电电压 （配置量）";
CM_ SG_ 2335895209 M2P_PermitMinVolt_B8_25 "汇流排8最低允许放电电压 （配置量）";
CM_ SG_ 2335895209 M2P_PermitMaxPow_Chg_B8_25 "汇流排8最大允许充电功率";
CM_ SG_ 2335895209 M2P_PermitMaxPow_DisChg_B8_25 "汇流排8最大允许放电功率";
CM_ SG_ 2335895210 M2P_PermitMaxVolt_B8_26 "汇流排8最高允许充电电压 （配置量）";
CM_ SG_ 2335895210 M2P_PermitMinVolt_B8_26 "汇流排8最低允许放电电压 （配置量）";
CM_ SG_ 2335895210 M2P_PermitMaxPow_Chg_B8_26 "汇流排8最大允许充电功率";
CM_ SG_ 2335895210 M2P_PermitMaxPow_DisChg_B8_26 "汇流排8最大允许放电功率";
CM_ SG_ 2335895211 M2P_PermitMaxVolt_B8_27 "汇流排8最高允许充电电压 （配置量）";
CM_ SG_ 2335895211 M2P_PermitMinVolt_B8_27 "汇流排8最低允许放电电压 （配置量）";
CM_ SG_ 2335895211 M2P_PermitMaxPow_Chg_B8_27 "汇流排8最大允许充电功率";
CM_ SG_ 2335895211 M2P_PermitMaxPow_DisChg_B8_27 "汇流排8最大允许放电功率";
CM_ SG_ 2335895212 M2P_PermitMaxVolt_B8_28 "汇流排8最高允许充电电压 （配置量）";
CM_ SG_ 2335895212 M2P_PermitMinVolt_B8_28 "汇流排8最低允许放电电压 （配置量）";
CM_ SG_ 2335895212 M2P_PermitMaxPow_Chg_B8_28 "汇流排8最大允许充电功率";
CM_ SG_ 2335895212 M2P_PermitMaxPow_DisChg_B8_28 "汇流排8最大允许放电功率";
CM_ SG_ 2335895213 M2P_PermitMaxVolt_B8_29 "汇流排8最高允许充电电压 （配置量）";
CM_ SG_ 2335895213 M2P_PermitMinVolt_B8_29 "汇流排8最低允许放电电压 （配置量）";
CM_ SG_ 2335895213 M2P_PermitMaxPow_Chg_B8_29 "汇流排8最大允许充电功率";
CM_ SG_ 2335895213 M2P_PermitMaxPow_DisChg_B8_29 "汇流排8最大允许放电功率";
CM_ SG_ 2335895214 M2P_PermitMaxVolt_B8_30 "汇流排8最高允许充电电压 （配置量）";
CM_ SG_ 2335895214 M2P_PermitMinVolt_B8_30 "汇流排8最低允许放电电压 （配置量）";
CM_ SG_ 2335895214 M2P_PermitMaxPow_Chg_B8_30 "汇流排8最大允许充电功率";
CM_ SG_ 2335895214 M2P_PermitMaxPow_DisChg_B8_30 "汇流排8最大允许放电功率";
CM_ SG_ 2335895215 M2P_PermitMaxVolt_B8_31 "汇流排8最高允许充电电压 （配置量）";
CM_ SG_ 2335895215 M2P_PermitMinVolt_B8_31 "汇流排8最低允许放电电压 （配置量）";
CM_ SG_ 2335895215 M2P_PermitMaxPow_Chg_B8_31 "汇流排8最大允许充电功率";
CM_ SG_ 2335895215 M2P_PermitMaxPow_DisChg_B8_31 "汇流排8最大允许放电功率";
CM_ SG_ 2335960721 M2P_Power_B8_01 "汇流排8实时功率";
CM_ SG_ 2335960721 M2P_SysremEngy_Chg_B8_01 "汇流排8充电剩余能量";
CM_ SG_ 2335960721 M2P_SysremEngy_DisChg_B8_01 "汇流排8放电剩余能量";
CM_ SG_ 2335960721 M2P_SysMaxVolt_B8_01 "汇流排8单体最大电压  ";
CM_ SG_ 2335960722 M2P_Power_B8_02 "汇流排8实时功率";
CM_ SG_ 2335960722 M2P_SysremEngy_Chg_B8_02 "汇流排8充电剩余能量";
CM_ SG_ 2335960722 M2P_SysremEngy_DisChg_B8_02 "汇流排8放电剩余能量";
CM_ SG_ 2335960722 M2P_SysMaxVolt_B8_02 "汇流排8单体最大电压  ";
CM_ SG_ 2335960723 M2P_Power_B8_03 "汇流排8实时功率";
CM_ SG_ 2335960723 M2P_SysremEngy_Chg_B8_03 "汇流排8充电剩余能量";
CM_ SG_ 2335960723 M2P_SysremEngy_DisChg_B8_03 "汇流排8放电剩余能量";
CM_ SG_ 2335960723 M2P_SysMaxVolt_B8_03 "汇流排8单体最大电压  ";
CM_ SG_ 2335960724 M2P_Power_B8_04 "汇流排8实时功率";
CM_ SG_ 2335960724 M2P_SysremEngy_Chg_B8_04 "汇流排8充电剩余能量";
CM_ SG_ 2335960724 M2P_SysremEngy_DisChg_B8_04 "汇流排8放电剩余能量";
CM_ SG_ 2335960724 M2P_SysMaxVolt_B8_04 "汇流排8单体最大电压  ";
CM_ SG_ 2335960725 M2P_Power_B8_05 "汇流排8实时功率";
CM_ SG_ 2335960725 M2P_SysremEngy_Chg_B8_05 "汇流排8充电剩余能量";
CM_ SG_ 2335960725 M2P_SysremEngy_DisChg_B8_05 "汇流排8放电剩余能量";
CM_ SG_ 2335960725 M2P_SysMaxVolt_B8_05 "汇流排8单体最大电压  ";
CM_ SG_ 2335960726 M2P_Power_B8_06 "汇流排8实时功率";
CM_ SG_ 2335960726 M2P_SysremEngy_Chg_B8_06 "汇流排8充电剩余能量";
CM_ SG_ 2335960726 M2P_SysremEngy_DisChg_B8_06 "汇流排8放电剩余能量";
CM_ SG_ 2335960726 M2P_SysMaxVolt_B8_06 "汇流排8单体最大电压  ";
CM_ SG_ 2335960727 M2P_Power_B8_07 "汇流排8实时功率";
CM_ SG_ 2335960727 M2P_SysremEngy_Chg_B8_07 "汇流排8充电剩余能量";
CM_ SG_ 2335960727 M2P_SysremEngy_DisChg_B8_07 "汇流排8放电剩余能量";
CM_ SG_ 2335960727 M2P_SysMaxVolt_B8_07 "汇流排8单体最大电压  ";
CM_ SG_ 2335960728 M2P_Power_B8_08 "汇流排8实时功率";
CM_ SG_ 2335960728 M2P_SysremEngy_Chg_B8_08 "汇流排8充电剩余能量";
CM_ SG_ 2335960728 M2P_SysremEngy_DisChg_B8_08 "汇流排8放电剩余能量";
CM_ SG_ 2335960728 M2P_SysMaxVolt_B8_08 "汇流排8单体最大电压  ";
CM_ SG_ 2335960729 M2P_Power_B8_09 "汇流排8实时功率";
CM_ SG_ 2335960729 M2P_SysremEngy_Chg_B8_09 "汇流排8充电剩余能量";
CM_ SG_ 2335960729 M2P_SysremEngy_DisChg_B8_09 "汇流排8放电剩余能量";
CM_ SG_ 2335960729 M2P_SysMaxVolt_B8_09 "汇流排8单体最大电压  ";
CM_ SG_ 2335960730 M2P_Power_B8_10 "汇流排8实时功率";
CM_ SG_ 2335960730 M2P_SysremEngy_Chg_B8_10 "汇流排8充电剩余能量";
CM_ SG_ 2335960730 M2P_SysremEngy_DisChg_B8_10 "汇流排8放电剩余能量";
CM_ SG_ 2335960730 M2P_SysMaxVolt_B8_10 "汇流排8单体最大电压  ";
CM_ SG_ 2335960731 M2P_Power_B8_11 "汇流排8实时功率";
CM_ SG_ 2335960731 M2P_SysremEngy_Chg_B8_11 "汇流排8充电剩余能量";
CM_ SG_ 2335960731 M2P_SysremEngy_DisChg_B8_11 "汇流排8放电剩余能量";
CM_ SG_ 2335960731 M2P_SysMaxVolt_B8_11 "汇流排8单体最大电压  ";
CM_ SG_ 2335960732 M2P_Power_B8_12 "汇流排8实时功率";
CM_ SG_ 2335960732 M2P_SysremEngy_Chg_B8_12 "汇流排8充电剩余能量";
CM_ SG_ 2335960732 M2P_SysremEngy_DisChg_B8_12 "汇流排8放电剩余能量";
CM_ SG_ 2335960732 M2P_SysMaxVolt_B8_12 "汇流排8单体最大电压  ";
CM_ SG_ 2335960733 M2P_Power_B8_13 "汇流排8实时功率";
CM_ SG_ 2335960733 M2P_SysremEngy_Chg_B8_13 "汇流排8充电剩余能量";
CM_ SG_ 2335960733 M2P_SysremEngy_DisChg_B8_13 "汇流排8放电剩余能量";
CM_ SG_ 2335960733 M2P_SysMaxVolt_B8_13 "汇流排8单体最大电压  ";
CM_ SG_ 2335960734 M2P_Power_B8_14 "汇流排8实时功率";
CM_ SG_ 2335960734 M2P_SysremEngy_Chg_B8_14 "汇流排8充电剩余能量";
CM_ SG_ 2335960734 M2P_SysremEngy_DisChg_B8_14 "汇流排8放电剩余能量";
CM_ SG_ 2335960734 M2P_SysMaxVolt_B8_14 "汇流排8单体最大电压  ";
CM_ SG_ 2335960735 M2P_Power_B8_15 "汇流排8实时功率";
CM_ SG_ 2335960735 M2P_SysremEngy_Chg_B8_15 "汇流排8充电剩余能量";
CM_ SG_ 2335960735 M2P_SysremEngy_DisChg_B8_15 "汇流排8放电剩余能量";
CM_ SG_ 2335960735 M2P_SysMaxVolt_B8_15 "汇流排8单体最大电压  ";
CM_ SG_ 2335960736 M2P_Power_B8_16 "汇流排8实时功率";
CM_ SG_ 2335960736 M2P_SysremEngy_Chg_B8_16 "汇流排8充电剩余能量";
CM_ SG_ 2335960736 M2P_SysremEngy_DisChg_B8_16 "汇流排8放电剩余能量";
CM_ SG_ 2335960736 M2P_SysMaxVolt_B8_16 "汇流排8单体最大电压  ";
CM_ SG_ 2335960737 M2P_Power_B8_17 "汇流排8实时功率";
CM_ SG_ 2335960737 M2P_SysremEngy_Chg_B8_17 "汇流排8充电剩余能量";
CM_ SG_ 2335960737 M2P_SysremEngy_DisChg_B8_17 "汇流排8放电剩余能量";
CM_ SG_ 2335960737 M2P_SysMaxVolt_B8_17 "汇流排8单体最大电压  ";
CM_ SG_ 2335960738 M2P_Power_B8_18 "汇流排8实时功率";
CM_ SG_ 2335960738 M2P_SysremEngy_Chg_B8_18 "汇流排8充电剩余能量";
CM_ SG_ 2335960738 M2P_SysremEngy_DisChg_B8_18 "汇流排8放电剩余能量";
CM_ SG_ 2335960738 M2P_SysMaxVolt_B8_18 "汇流排8单体最大电压  ";
CM_ SG_ 2335960739 M2P_Power_B8_19 "汇流排8实时功率";
CM_ SG_ 2335960739 M2P_SysremEngy_Chg_B8_19 "汇流排8充电剩余能量";
CM_ SG_ 2335960739 M2P_SysremEngy_DisChg_B8_19 "汇流排8放电剩余能量";
CM_ SG_ 2335960739 M2P_SysMaxVolt_B8_19 "汇流排8单体最大电压  ";
CM_ SG_ 2335960740 M2P_Power_B8_20 "汇流排8实时功率";
CM_ SG_ 2335960740 M2P_SysremEngy_Chg_B8_20 "汇流排8充电剩余能量";
CM_ SG_ 2335960740 M2P_SysremEngy_DisChg_B8_20 "汇流排8放电剩余能量";
CM_ SG_ 2335960740 M2P_SysMaxVolt_B8_20 "汇流排8单体最大电压  ";
CM_ SG_ 2335960741 M2P_Power_B8_21 "汇流排8实时功率";
CM_ SG_ 2335960741 M2P_SysremEngy_Chg_B8_21 "汇流排8充电剩余能量";
CM_ SG_ 2335960741 M2P_SysremEngy_DisChg_B8_21 "汇流排8放电剩余能量";
CM_ SG_ 2335960741 M2P_SysMaxVolt_B8_21 "汇流排8单体最大电压  ";
CM_ SG_ 2335960742 M2P_Power_B8_22 "汇流排8实时功率";
CM_ SG_ 2335960742 M2P_SysremEngy_Chg_B8_22 "汇流排8充电剩余能量";
CM_ SG_ 2335960742 M2P_SysremEngy_DisChg_B8_22 "汇流排8放电剩余能量";
CM_ SG_ 2335960742 M2P_SysMaxVolt_B8_22 "汇流排8单体最大电压  ";
CM_ SG_ 2335960743 M2P_Power_B8_23 "汇流排8实时功率";
CM_ SG_ 2335960743 M2P_SysremEngy_Chg_B8_23 "汇流排8充电剩余能量";
CM_ SG_ 2335960743 M2P_SysremEngy_DisChg_B8_23 "汇流排8放电剩余能量";
CM_ SG_ 2335960743 M2P_SysMaxVolt_B8_23 "汇流排8单体最大电压  ";
CM_ SG_ 2335960744 M2P_Power_B8_24 "汇流排8实时功率";
CM_ SG_ 2335960744 M2P_SysremEngy_Chg_B8_24 "汇流排8充电剩余能量";
CM_ SG_ 2335960744 M2P_SysremEngy_DisChg_B8_24 "汇流排8放电剩余能量";
CM_ SG_ 2335960744 M2P_SysMaxVolt_B8_24 "汇流排8单体最大电压  ";
CM_ SG_ 2335960745 M2P_Power_B8_25 "汇流排8实时功率";
CM_ SG_ 2335960745 M2P_SysremEngy_Chg_B8_25 "汇流排8充电剩余能量";
CM_ SG_ 2335960745 M2P_SysremEngy_DisChg_B8_25 "汇流排8放电剩余能量";
CM_ SG_ 2335960745 M2P_SysMaxVolt_B8_25 "汇流排8单体最大电压  ";
CM_ SG_ 2335960746 M2P_Power_B8_26 "汇流排8实时功率";
CM_ SG_ 2335960746 M2P_SysremEngy_Chg_B8_26 "汇流排8充电剩余能量";
CM_ SG_ 2335960746 M2P_SysremEngy_DisChg_B8_26 "汇流排8放电剩余能量";
CM_ SG_ 2335960746 M2P_SysMaxVolt_B8_26 "汇流排8单体最大电压  ";
CM_ SG_ 2335960747 M2P_Power_B8_27 "汇流排8实时功率";
CM_ SG_ 2335960747 M2P_SysremEngy_Chg_B8_27 "汇流排8充电剩余能量";
CM_ SG_ 2335960747 M2P_SysremEngy_DisChg_B8_27 "汇流排8放电剩余能量";
CM_ SG_ 2335960747 M2P_SysMaxVolt_B8_27 "汇流排8单体最大电压  ";
CM_ SG_ 2335960748 M2P_Power_B8_28 "汇流排8实时功率";
CM_ SG_ 2335960748 M2P_SysremEngy_Chg_B8_28 "汇流排8充电剩余能量";
CM_ SG_ 2335960748 M2P_SysremEngy_DisChg_B8_28 "汇流排8放电剩余能量";
CM_ SG_ 2335960748 M2P_SysMaxVolt_B8_28 "汇流排8单体最大电压  ";
CM_ SG_ 2335960749 M2P_Power_B8_29 "汇流排8实时功率";
CM_ SG_ 2335960749 M2P_SysremEngy_Chg_B8_29 "汇流排8充电剩余能量";
CM_ SG_ 2335960749 M2P_SysremEngy_DisChg_B8_29 "汇流排8放电剩余能量";
CM_ SG_ 2335960749 M2P_SysMaxVolt_B8_29 "汇流排8单体最大电压  ";
CM_ SG_ 2335960750 M2P_Power_B8_30 "汇流排8实时功率";
CM_ SG_ 2335960750 M2P_SysremEngy_Chg_B8_30 "汇流排8充电剩余能量";
CM_ SG_ 2335960750 M2P_SysremEngy_DisChg_B8_30 "汇流排8放电剩余能量";
CM_ SG_ 2335960750 M2P_SysMaxVolt_B8_30 "汇流排8单体最大电压  ";
CM_ SG_ 2335960751 M2P_Power_B8_31 "汇流排8实时功率";
CM_ SG_ 2335960751 M2P_SysremEngy_Chg_B8_31 "汇流排8充电剩余能量";
CM_ SG_ 2335960751 M2P_SysremEngy_DisChg_B8_31 "汇流排8放电剩余能量";
CM_ SG_ 2335960751 M2P_SysMaxVolt_B8_31 "汇流排8单体最大电压  ";
CM_ SG_ 2336026257 M2P_SysMinVolt_B8_01 "汇流排8单体最小电压";
CM_ SG_ 2336026257 M2P_SysAvgVolt_B8_01 "汇流排8单体平均电压";
CM_ SG_ 2336026257 M2P_BMS_Status_B8 "汇流排8能量状态";
CM_ SG_ 2336026257 M2P_SOC_B8 "汇流排8系统SOC";
CM_ SG_ 2336026257 M2P_SOH_B8 "汇流排8系统SOH";
CM_ SG_ 2336026257 Reserved_01 "预留";
CM_ SG_ 2336026258 M2P_SysMinVolt_B8_02 "汇流排8单体最小电压";
CM_ SG_ 2336026258 M2P_SysAvgVolt_B8_02 "汇流排8单体平均电压";
CM_ SG_ 2336026258 M2P_BMS_Status_B8 "汇流排8能量状态";
CM_ SG_ 2336026258 M2P_SOC_B8 "汇流排8系统SOC";
CM_ SG_ 2336026258 M2P_SOH_B8 "汇流排8系统SOH";
CM_ SG_ 2336026258 Reserved_02 "预留";
CM_ SG_ 2336026259 M2P_SysMinVolt_B8_03 "汇流排8单体最小电压";
CM_ SG_ 2336026259 M2P_SysAvgVolt_B8_03 "汇流排8单体平均电压";
CM_ SG_ 2336026259 M2P_BMS_Status_B8 "汇流排8能量状态";
CM_ SG_ 2336026259 M2P_SOC_B8 "汇流排8系统SOC";
CM_ SG_ 2336026259 M2P_SOH_B8 "汇流排8系统SOH";
CM_ SG_ 2336026259 Reserved_03 "预留";
CM_ SG_ 2336026260 M2P_SysMinVolt_B8_04 "汇流排8单体最小电压";
CM_ SG_ 2336026260 M2P_SysAvgVolt_B8_04 "汇流排8单体平均电压";
CM_ SG_ 2336026260 M2P_BMS_Status_B8 "汇流排8能量状态";
CM_ SG_ 2336026260 M2P_SOC_B8 "汇流排8系统SOC";
CM_ SG_ 2336026260 M2P_SOH_B8 "汇流排8系统SOH";
CM_ SG_ 2336026260 Reserved_04 "预留";
CM_ SG_ 2336026261 M2P_SysMinVolt_B8_05 "汇流排8单体最小电压";
CM_ SG_ 2336026261 M2P_SysAvgVolt_B8_05 "汇流排8单体平均电压";
CM_ SG_ 2336026261 M2P_BMS_Status_B8 "汇流排8能量状态";
CM_ SG_ 2336026261 M2P_SOC_B8 "汇流排8系统SOC";
CM_ SG_ 2336026261 M2P_SOH_B8 "汇流排8系统SOH";
CM_ SG_ 2336026261 Reserved_05 "预留";
CM_ SG_ 2336026262 M2P_SysMinVolt_B8_06 "汇流排8单体最小电压";
CM_ SG_ 2336026262 M2P_SysAvgVolt_B8_06 "汇流排8单体平均电压";
CM_ SG_ 2336026262 M2P_BMS_Status_B8 "汇流排8能量状态";
CM_ SG_ 2336026262 M2P_SOC_B8 "汇流排8系统SOC";
CM_ SG_ 2336026262 M2P_SOH_B8 "汇流排8系统SOH";
CM_ SG_ 2336026262 Reserved_06 "预留";
CM_ SG_ 2336026263 M2P_SysMinVolt_B8_07 "汇流排8单体最小电压";
CM_ SG_ 2336026263 M2P_SysAvgVolt_B8_07 "汇流排8单体平均电压";
CM_ SG_ 2336026263 M2P_BMS_Status_B8 "汇流排8能量状态";
CM_ SG_ 2336026263 M2P_SOC_B8 "汇流排8系统SOC";
CM_ SG_ 2336026263 M2P_SOH_B8 "汇流排8系统SOH";
CM_ SG_ 2336026263 Reserved_07 "预留";
CM_ SG_ 2336026264 M2P_SysMinVolt_B8_08 "汇流排8单体最小电压";
CM_ SG_ 2336026264 M2P_SysAvgVolt_B8_08 "汇流排8单体平均电压";
CM_ SG_ 2336026264 M2P_BMS_Status_B8 "汇流排8能量状态";
CM_ SG_ 2336026264 M2P_SOC_B8 "汇流排8系统SOC";
CM_ SG_ 2336026264 M2P_SOH_B8 "汇流排8系统SOH";
CM_ SG_ 2336026264 Reserved_08 "预留";
CM_ SG_ 2336026265 M2P_SysMinVolt_B8_09 "汇流排8单体最小电压";
CM_ SG_ 2336026265 M2P_SysAvgVolt_B8_09 "汇流排8单体平均电压";
CM_ SG_ 2336026265 M2P_BMS_Status_B8 "汇流排8能量状态";
CM_ SG_ 2336026265 M2P_SOC_B8 "汇流排8系统SOC";
CM_ SG_ 2336026265 M2P_SOH_B8 "汇流排8系统SOH";
CM_ SG_ 2336026265 Reserved_09 "预留";
CM_ SG_ 2336026266 M2P_SysMinVolt_B8_10 "汇流排8单体最小电压";
CM_ SG_ 2336026266 M2P_SysAvgVolt_B8_10 "汇流排8单体平均电压";
CM_ SG_ 2336026266 M2P_BMS_Status_B8 "汇流排8能量状态";
CM_ SG_ 2336026266 M2P_SOC_B8 "汇流排8系统SOC";
CM_ SG_ 2336026266 M2P_SOH_B8 "汇流排8系统SOH";
CM_ SG_ 2336026266 Reserved_10 "预留";
CM_ SG_ 2336026267 M2P_SysMinVolt_B8_11 "汇流排8单体最小电压";
CM_ SG_ 2336026267 M2P_SysAvgVolt_B8_11 "汇流排8单体平均电压";
CM_ SG_ 2336026267 M2P_BMS_Status_B8 "汇流排8能量状态";
CM_ SG_ 2336026267 M2P_SOC_B8 "汇流排8系统SOC";
CM_ SG_ 2336026267 M2P_SOH_B8 "汇流排8系统SOH";
CM_ SG_ 2336026267 Reserved_11 "预留";
CM_ SG_ 2336026268 M2P_SysMinVolt_B8_12 "汇流排8单体最小电压";
CM_ SG_ 2336026268 M2P_SysAvgVolt_B8_12 "汇流排8单体平均电压";
CM_ SG_ 2336026268 M2P_BMS_Status_B8 "汇流排8能量状态";
CM_ SG_ 2336026268 M2P_SOC_B8 "汇流排8系统SOC";
CM_ SG_ 2336026268 M2P_SOH_B8 "汇流排8系统SOH";
CM_ SG_ 2336026268 Reserved_12 "预留";
CM_ SG_ 2336026269 M2P_SysMinVolt_B8_13 "汇流排8单体最小电压";
CM_ SG_ 2336026269 M2P_SysAvgVolt_B8_13 "汇流排8单体平均电压";
CM_ SG_ 2336026269 M2P_BMS_Status_B8 "汇流排8能量状态";
CM_ SG_ 2336026269 M2P_SOC_B8 "汇流排8系统SOC";
CM_ SG_ 2336026269 M2P_SOH_B8 "汇流排8系统SOH";
CM_ SG_ 2336026269 Reserved_13 "预留";
CM_ SG_ 2336026270 M2P_SysMinVolt_B8_14 "汇流排8单体最小电压";
CM_ SG_ 2336026270 M2P_SysAvgVolt_B8_14 "汇流排8单体平均电压";
CM_ SG_ 2336026270 M2P_BMS_Status_B8 "汇流排8能量状态";
CM_ SG_ 2336026270 M2P_SOC_B8 "汇流排8系统SOC";
CM_ SG_ 2336026270 M2P_SOH_B8 "汇流排8系统SOH";
CM_ SG_ 2336026270 Reserved_14 "预留";
CM_ SG_ 2336026271 M2P_SysMinVolt_B8_15 "汇流排8单体最小电压";
CM_ SG_ 2336026271 M2P_SysAvgVolt_B8_15 "汇流排8单体平均电压";
CM_ SG_ 2336026271 M2P_BMS_Status_B8 "汇流排8能量状态";
CM_ SG_ 2336026271 M2P_SOC_B8 "汇流排8系统SOC";
CM_ SG_ 2336026271 M2P_SOH_B8 "汇流排8系统SOH";
CM_ SG_ 2336026271 Reserved_15 "预留";
CM_ SG_ 2336026272 M2P_SysMinVolt_B8_16 "汇流排8单体最小电压";
CM_ SG_ 2336026272 M2P_SysAvgVolt_B8_16 "汇流排8单体平均电压";
CM_ SG_ 2336026272 M2P_BMS_Status_B8 "汇流排8能量状态";
CM_ SG_ 2336026272 M2P_SOC_B8 "汇流排8系统SOC";
CM_ SG_ 2336026272 M2P_SOH_B8 "汇流排8系统SOH";
CM_ SG_ 2336026272 Reserved_16 "预留";
CM_ SG_ 2336026273 M2P_SysMinVolt_B8_17 "汇流排8单体最小电压";
CM_ SG_ 2336026273 M2P_SysAvgVolt_B8_17 "汇流排8单体平均电压";
CM_ SG_ 2336026273 M2P_BMS_Status_B8 "汇流排8能量状态";
CM_ SG_ 2336026273 M2P_SOC_B8 "汇流排8系统SOC";
CM_ SG_ 2336026273 M2P_SOH_B8 "汇流排8系统SOH";
CM_ SG_ 2336026273 Reserved_17 "预留";
CM_ SG_ 2336026274 M2P_SysMinVolt_B8_18 "汇流排8单体最小电压";
CM_ SG_ 2336026274 M2P_SysAvgVolt_B8_18 "汇流排8单体平均电压";
CM_ SG_ 2336026274 M2P_BMS_Status_B8 "汇流排8能量状态";
CM_ SG_ 2336026274 M2P_SOC_B8 "汇流排8系统SOC";
CM_ SG_ 2336026274 M2P_SOH_B8 "汇流排8系统SOH";
CM_ SG_ 2336026274 Reserved_18 "预留";
CM_ SG_ 2336026275 M2P_SysMinVolt_B8_19 "汇流排8单体最小电压";
CM_ SG_ 2336026275 M2P_SysAvgVolt_B8_19 "汇流排8单体平均电压";
CM_ SG_ 2336026275 M2P_BMS_Status_B8 "汇流排8能量状态";
CM_ SG_ 2336026275 M2P_SOC_B8 "汇流排8系统SOC";
CM_ SG_ 2336026275 M2P_SOH_B8 "汇流排8系统SOH";
CM_ SG_ 2336026275 Reserved_19 "预留";
CM_ SG_ 2336026276 M2P_SysMinVolt_B8_20 "汇流排8单体最小电压";
CM_ SG_ 2336026276 M2P_SysAvgVolt_B8_20 "汇流排8单体平均电压";
CM_ SG_ 2336026276 M2P_BMS_Status_B8 "汇流排8能量状态";
CM_ SG_ 2336026276 M2P_SOC_B8 "汇流排8系统SOC";
CM_ SG_ 2336026276 M2P_SOH_B8 "汇流排8系统SOH";
CM_ SG_ 2336026276 Reserved_20 "预留";
CM_ SG_ 2336026277 M2P_SysMinVolt_B8_21 "汇流排8单体最小电压";
CM_ SG_ 2336026277 M2P_SysAvgVolt_B8_21 "汇流排8单体平均电压";
CM_ SG_ 2336026277 M2P_BMS_Status_B8 "汇流排8能量状态";
CM_ SG_ 2336026277 M2P_SOC_B8 "汇流排8系统SOC";
CM_ SG_ 2336026277 M2P_SOH_B8 "汇流排8系统SOH";
CM_ SG_ 2336026277 Reserved_21 "预留";
CM_ SG_ 2336026278 M2P_SysMinVolt_B8_22 "汇流排8单体最小电压";
CM_ SG_ 2336026278 M2P_SysAvgVolt_B8_22 "汇流排8单体平均电压";
CM_ SG_ 2336026278 M2P_BMS_Status_B8 "汇流排8能量状态";
CM_ SG_ 2336026278 M2P_SOC_B8 "汇流排8系统SOC";
CM_ SG_ 2336026278 M2P_SOH_B8 "汇流排8系统SOH";
CM_ SG_ 2336026278 Reserved_22 "预留";
CM_ SG_ 2336026279 M2P_SysMinVolt_B8_23 "汇流排8单体最小电压";
CM_ SG_ 2336026279 M2P_SysAvgVolt_B8_23 "汇流排8单体平均电压";
CM_ SG_ 2336026279 M2P_BMS_Status_B8 "汇流排8能量状态";
CM_ SG_ 2336026279 M2P_SOC_B8 "汇流排8系统SOC";
CM_ SG_ 2336026279 M2P_SOH_B8 "汇流排8系统SOH";
CM_ SG_ 2336026279 Reserved_23 "预留";
CM_ SG_ 2336026280 M2P_SysMinVolt_B8_24 "汇流排8单体最小电压";
CM_ SG_ 2336026280 M2P_SysAvgVolt_B8_24 "汇流排8单体平均电压";
CM_ SG_ 2336026280 M2P_BMS_Status_B8 "汇流排8能量状态";
CM_ SG_ 2336026280 M2P_SOC_B8 "汇流排8系统SOC";
CM_ SG_ 2336026280 M2P_SOH_B8 "汇流排8系统SOH";
CM_ SG_ 2336026280 Reserved_24 "预留";
CM_ SG_ 2336026281 M2P_SysMinVolt_B8_25 "汇流排8单体最小电压";
CM_ SG_ 2336026281 M2P_SysAvgVolt_B8_25 "汇流排8单体平均电压";
CM_ SG_ 2336026281 M2P_BMS_Status_B8 "汇流排8能量状态";
CM_ SG_ 2336026281 M2P_SOC_B8 "汇流排8系统SOC";
CM_ SG_ 2336026281 M2P_SOH_B8 "汇流排8系统SOH";
CM_ SG_ 2336026281 Reserved_25 "预留";
CM_ SG_ 2336026282 M2P_SysMinVolt_B8_26 "汇流排8单体最小电压";
CM_ SG_ 2336026282 M2P_SysAvgVolt_B8_26 "汇流排8单体平均电压";
CM_ SG_ 2336026282 M2P_BMS_Status_B8 "汇流排8能量状态";
CM_ SG_ 2336026282 M2P_SOC_B8 "汇流排8系统SOC";
CM_ SG_ 2336026282 M2P_SOH_B8 "汇流排8系统SOH";
CM_ SG_ 2336026282 Reserved_26 "预留";
CM_ SG_ 2336026283 M2P_SysMinVolt_B8_27 "汇流排8单体最小电压";
CM_ SG_ 2336026283 M2P_SysAvgVolt_B8_27 "汇流排8单体平均电压";
CM_ SG_ 2336026283 M2P_BMS_Status_B8 "汇流排8能量状态";
CM_ SG_ 2336026283 M2P_SOC_B8 "汇流排8系统SOC";
CM_ SG_ 2336026283 M2P_SOH_B8 "汇流排8系统SOH";
CM_ SG_ 2336026283 Reserved_27 "预留";
CM_ SG_ 2336026284 M2P_SysMinVolt_B8_28 "汇流排8单体最小电压";
CM_ SG_ 2336026284 M2P_SysAvgVolt_B8_28 "汇流排8单体平均电压";
CM_ SG_ 2336026284 M2P_BMS_Status_B8 "汇流排8能量状态";
CM_ SG_ 2336026284 M2P_SOC_B8 "汇流排8系统SOC";
CM_ SG_ 2336026284 M2P_SOH_B8 "汇流排8系统SOH";
CM_ SG_ 2336026284 Reserved_28 "预留";
CM_ SG_ 2336026285 M2P_SysMinVolt_B8_29 "汇流排8单体最小电压";
CM_ SG_ 2336026285 M2P_SysAvgVolt_B8_29 "汇流排8单体平均电压";
CM_ SG_ 2336026285 M2P_BMS_Status_B8 "汇流排8能量状态";
CM_ SG_ 2336026285 M2P_SOC_B8 "汇流排8系统SOC";
CM_ SG_ 2336026285 M2P_SOH_B8 "汇流排8系统SOH";
CM_ SG_ 2336026285 Reserved_29 "预留";
CM_ SG_ 2336026286 M2P_SysMinVolt_B8_30 "汇流排8单体最小电压";
CM_ SG_ 2336026286 M2P_SysAvgVolt_B8_30 "汇流排8单体平均电压";
CM_ SG_ 2336026286 M2P_BMS_Status_B8 "汇流排8能量状态";
CM_ SG_ 2336026286 M2P_SOC_B8 "汇流排8系统SOC";
CM_ SG_ 2336026286 M2P_SOH_B8 "汇流排8系统SOH";
CM_ SG_ 2336026286 Reserved_30 "预留";
CM_ SG_ 2336026287 M2P_SysMinVolt_B8_31 "汇流排8单体最小电压";
CM_ SG_ 2336026287 M2P_SysAvgVolt_B8_31 "汇流排8单体平均电压";
CM_ SG_ 2336026287 M2P_BMS_Status_B8 "汇流排8能量状态";
CM_ SG_ 2336026287 M2P_SOC_B8 "汇流排8系统SOC";
CM_ SG_ 2336026287 M2P_SOH_B8 "汇流排8系统SOH";
CM_ SG_ 2336026287 Reserved_31 "预留";
CM_ SG_ 2336091793 M2P_SOE_Charge_B8 "汇流排8系可充电SOE";
CM_ SG_ 2336091793 M2P_SOE_Discharge_B8 "汇流排8系可放电SOE";
CM_ SG_ 2336091793 Reserved_01 "预留";
CM_ SG_ 2336091794 M2P_SOE_Charge_B8 "汇流排8系可充电SOE";
CM_ SG_ 2336091794 M2P_SOE_Discharge_B8 "汇流排8系可放电SOE";
CM_ SG_ 2336091794 Reserved_02 "预留";
CM_ SG_ 2336091795 M2P_SOE_Charge_B8 "汇流排8系可充电SOE";
CM_ SG_ 2336091795 M2P_SOE_Discharge_B8 "汇流排8系可放电SOE";
CM_ SG_ 2336091795 Reserved_03 "预留";
CM_ SG_ 2336091796 M2P_SOE_Charge_B8 "汇流排8系可充电SOE";
CM_ SG_ 2336091796 M2P_SOE_Discharge_B8 "汇流排8系可放电SOE";
CM_ SG_ 2336091796 Reserved_04 "预留";
CM_ SG_ 2336091797 M2P_SOE_Charge_B8 "汇流排8系可充电SOE";
CM_ SG_ 2336091797 M2P_SOE_Discharge_B8 "汇流排8系可放电SOE";
CM_ SG_ 2336091797 Reserved_05 "预留";
CM_ SG_ 2336091798 M2P_SOE_Charge_B8 "汇流排8系可充电SOE";
CM_ SG_ 2336091798 M2P_SOE_Discharge_B8 "汇流排8系可放电SOE";
CM_ SG_ 2336091798 Reserved_06 "预留";
CM_ SG_ 2336091799 M2P_SOE_Charge_B8 "汇流排8系可充电SOE";
CM_ SG_ 2336091799 M2P_SOE_Discharge_B8 "汇流排8系可放电SOE";
CM_ SG_ 2336091799 Reserved_07 "预留";
CM_ SG_ 2336091800 M2P_SOE_Charge_B8 "汇流排8系可充电SOE";
CM_ SG_ 2336091800 M2P_SOE_Discharge_B8 "汇流排8系可放电SOE";
CM_ SG_ 2336091800 Reserved_08 "预留";
CM_ SG_ 2336091801 M2P_SOE_Charge_B8 "汇流排8系可充电SOE";
CM_ SG_ 2336091801 M2P_SOE_Discharge_B8 "汇流排8系可放电SOE";
CM_ SG_ 2336091801 Reserved_09 "预留";
CM_ SG_ 2336091802 M2P_SOE_Charge_B8 "汇流排8系可充电SOE";
CM_ SG_ 2336091802 M2P_SOE_Discharge_B8 "汇流排8系可放电SOE";
CM_ SG_ 2336091802 Reserved_10 "预留";
CM_ SG_ 2336091803 M2P_SOE_Charge_B8 "汇流排8系可充电SOE";
CM_ SG_ 2336091803 M2P_SOE_Discharge_B8 "汇流排8系可放电SOE";
CM_ SG_ 2336091803 Reserved_11 "预留";
CM_ SG_ 2336091804 M2P_SOE_Charge_B8 "汇流排8系可充电SOE";
CM_ SG_ 2336091804 M2P_SOE_Discharge_B8 "汇流排8系可放电SOE";
CM_ SG_ 2336091804 Reserved_12 "预留";
CM_ SG_ 2336091805 M2P_SOE_Charge_B8 "汇流排8系可充电SOE";
CM_ SG_ 2336091805 M2P_SOE_Discharge_B8 "汇流排8系可放电SOE";
CM_ SG_ 2336091805 Reserved_13 "预留";
CM_ SG_ 2336091806 M2P_SOE_Charge_B8 "汇流排8系可充电SOE";
CM_ SG_ 2336091806 M2P_SOE_Discharge_B8 "汇流排8系可放电SOE";
CM_ SG_ 2336091806 Reserved_14 "预留";
CM_ SG_ 2336091807 M2P_SOE_Charge_B8 "汇流排8系可充电SOE";
CM_ SG_ 2336091807 M2P_SOE_Discharge_B8 "汇流排8系可放电SOE";
CM_ SG_ 2336091807 Reserved_15 "预留";
CM_ SG_ 2336091808 M2P_SOE_Charge_B8 "汇流排8系可充电SOE";
CM_ SG_ 2336091808 M2P_SOE_Discharge_B8 "汇流排8系可放电SOE";
CM_ SG_ 2336091808 Reserved_16 "预留";
CM_ SG_ 2336091809 M2P_SOE_Charge_B8 "汇流排8系可充电SOE";
CM_ SG_ 2336091809 M2P_SOE_Discharge_B8 "汇流排8系可放电SOE";
CM_ SG_ 2336091809 Reserved_17 "预留";
CM_ SG_ 2336091810 M2P_SOE_Charge_B8 "汇流排8系可充电SOE";
CM_ SG_ 2336091810 M2P_SOE_Discharge_B8 "汇流排8系可放电SOE";
CM_ SG_ 2336091810 Reserved_18 "预留";
CM_ SG_ 2336091811 M2P_SOE_Charge_B8 "汇流排8系可充电SOE";
CM_ SG_ 2336091811 M2P_SOE_Discharge_B8 "汇流排8系可放电SOE";
CM_ SG_ 2336091811 Reserved_19 "预留";
CM_ SG_ 2336091812 M2P_SOE_Charge_B8 "汇流排8系可充电SOE";
CM_ SG_ 2336091812 M2P_SOE_Discharge_B8 "汇流排8系可放电SOE";
CM_ SG_ 2336091812 Reserved_20 "预留";
CM_ SG_ 2336091813 M2P_SOE_Charge_B8 "汇流排8系可充电SOE";
CM_ SG_ 2336091813 M2P_SOE_Discharge_B8 "汇流排8系可放电SOE";
CM_ SG_ 2336091813 Reserved_21 "预留";
CM_ SG_ 2336091814 M2P_SOE_Charge_B8 "汇流排8系可充电SOE";
CM_ SG_ 2336091814 M2P_SOE_Discharge_B8 "汇流排8系可放电SOE";
CM_ SG_ 2336091814 Reserved_22 "预留";
CM_ SG_ 2336091815 M2P_SOE_Charge_B8 "汇流排8系可充电SOE";
CM_ SG_ 2336091815 M2P_SOE_Discharge_B8 "汇流排8系可放电SOE";
CM_ SG_ 2336091815 Reserved_23 "预留";
CM_ SG_ 2336091816 M2P_SOE_Charge_B8 "汇流排8系可充电SOE";
CM_ SG_ 2336091816 M2P_SOE_Discharge_B8 "汇流排8系可放电SOE";
CM_ SG_ 2336091816 Reserved_24 "预留";
CM_ SG_ 2336091817 M2P_SOE_Charge_B8 "汇流排8系可充电SOE";
CM_ SG_ 2336091817 M2P_SOE_Discharge_B8 "汇流排8系可放电SOE";
CM_ SG_ 2336091817 Reserved_25 "预留";
CM_ SG_ 2336091818 M2P_SOE_Charge_B8 "汇流排8系可充电SOE";
CM_ SG_ 2336091818 M2P_SOE_Discharge_B8 "汇流排8系可放电SOE";
CM_ SG_ 2336091818 Reserved_26 "预留";
CM_ SG_ 2336091819 M2P_SOE_Charge_B8 "汇流排8系可充电SOE";
CM_ SG_ 2336091819 M2P_SOE_Discharge_B8 "汇流排8系可放电SOE";
CM_ SG_ 2336091819 Reserved_27 "预留";
CM_ SG_ 2336091820 M2P_SOE_Charge_B8 "汇流排8系可充电SOE";
CM_ SG_ 2336091820 M2P_SOE_Discharge_B8 "汇流排8系可放电SOE";
CM_ SG_ 2336091820 Reserved_28 "预留";
CM_ SG_ 2336091821 M2P_SOE_Charge_B8 "汇流排8系可充电SOE";
CM_ SG_ 2336091821 M2P_SOE_Discharge_B8 "汇流排8系可放电SOE";
CM_ SG_ 2336091821 Reserved_29 "预留";
CM_ SG_ 2336091822 M2P_SOE_Charge_B8 "汇流排8系可充电SOE";
CM_ SG_ 2336091822 M2P_SOE_Discharge_B8 "汇流排8系可放电SOE";
CM_ SG_ 2336091822 Reserved_30 "预留";
CM_ SG_ 2336091823 M2P_SOE_Charge_B8 "汇流排8系可充电SOE";
CM_ SG_ 2336091823 M2P_SOE_Discharge_B8 "汇流排8系可放电SOE";
CM_ SG_ 2336091823 Reserved_31 "预留";
CM_ SG_ 2336157329 M2P_Measure_Vol_B9_01 "汇流排9所有高压在线电柜外侧电压平均值    ";
CM_ SG_ 2336157329 M2P_Current_B9_01 "汇流排9所有电柜电流累加和";
CM_ SG_ 2336157329 M2P_PermitMaxCharge_I_B9_01 "汇流排9最大允许充电电流";
CM_ SG_ 2336157329 M2P_PermitMaxDisCharge_I_B9_01 "汇流排9最大允许放电电流";
CM_ SG_ 2336157330 M2P_Measure_Vol_B9_02 "汇流排9所有高压在线电柜外侧电压平均值    ";
CM_ SG_ 2336157330 M2P_Current_B9_02 "汇流排9所有电柜电流累加和";
CM_ SG_ 2336157330 M2P_PermitMaxCharge_I_B9_02 "汇流排9最大允许充电电流";
CM_ SG_ 2336157330 M2P_PermitMaxDisCharge_I_B9_02 "汇流排9最大允许放电电流";
CM_ SG_ 2336157331 M2P_Measure_Vol_B9_03 "汇流排9所有高压在线电柜外侧电压平均值    ";
CM_ SG_ 2336157331 M2P_Current_B9_03 "汇流排9所有电柜电流累加和";
CM_ SG_ 2336157331 M2P_PermitMaxCharge_I_B9_03 "汇流排9最大允许充电电流";
CM_ SG_ 2336157331 M2P_PermitMaxDisCharge_I_B9_03 "汇流排9最大允许放电电流";
CM_ SG_ 2336157332 M2P_Measure_Vol_B9_04 "汇流排9所有高压在线电柜外侧电压平均值    ";
CM_ SG_ 2336157332 M2P_Current_B9_04 "汇流排9所有电柜电流累加和";
CM_ SG_ 2336157332 M2P_PermitMaxCharge_I_B9_04 "汇流排9最大允许充电电流";
CM_ SG_ 2336157332 M2P_PermitMaxDisCharge_I_B9_04 "汇流排9最大允许放电电流";
CM_ SG_ 2336157333 M2P_Measure_Vol_B9_05 "汇流排9所有高压在线电柜外侧电压平均值    ";
CM_ SG_ 2336157333 M2P_Current_B9_05 "汇流排9所有电柜电流累加和";
CM_ SG_ 2336157333 M2P_PermitMaxCharge_I_B9_05 "汇流排9最大允许充电电流";
CM_ SG_ 2336157333 M2P_PermitMaxDisCharge_I_B9_05 "汇流排9最大允许放电电流";
CM_ SG_ 2336157334 M2P_Measure_Vol_B9_06 "汇流排9所有高压在线电柜外侧电压平均值    ";
CM_ SG_ 2336157334 M2P_Current_B9_06 "汇流排9所有电柜电流累加和";
CM_ SG_ 2336157334 M2P_PermitMaxCharge_I_B9_06 "汇流排9最大允许充电电流";
CM_ SG_ 2336157334 M2P_PermitMaxDisCharge_I_B9_06 "汇流排9最大允许放电电流";
CM_ SG_ 2336157335 M2P_Measure_Vol_B9_07 "汇流排9所有高压在线电柜外侧电压平均值    ";
CM_ SG_ 2336157335 M2P_Current_B9_07 "汇流排9所有电柜电流累加和";
CM_ SG_ 2336157335 M2P_PermitMaxCharge_I_B9_07 "汇流排9最大允许充电电流";
CM_ SG_ 2336157335 M2P_PermitMaxDisCharge_I_B9_07 "汇流排9最大允许放电电流";
CM_ SG_ 2336157336 M2P_Measure_Vol_B9_08 "汇流排9所有高压在线电柜外侧电压平均值    ";
CM_ SG_ 2336157336 M2P_Current_B9_08 "汇流排9所有电柜电流累加和";
CM_ SG_ 2336157336 M2P_PermitMaxCharge_I_B9_08 "汇流排9最大允许充电电流";
CM_ SG_ 2336157336 M2P_PermitMaxDisCharge_I_B9_08 "汇流排9最大允许放电电流";
CM_ SG_ 2336157337 M2P_Measure_Vol_B9_09 "汇流排9所有高压在线电柜外侧电压平均值    ";
CM_ SG_ 2336157337 M2P_Current_B9_09 "汇流排9所有电柜电流累加和";
CM_ SG_ 2336157337 M2P_PermitMaxCharge_I_B9_09 "汇流排9最大允许充电电流";
CM_ SG_ 2336157337 M2P_PermitMaxDisCharge_I_B9_09 "汇流排9最大允许放电电流";
CM_ SG_ 2336157338 M2P_Measure_Vol_B9_10 "汇流排9所有高压在线电柜外侧电压平均值    ";
CM_ SG_ 2336157338 M2P_Current_B9_10 "汇流排9所有电柜电流累加和";
CM_ SG_ 2336157338 M2P_PermitMaxCharge_I_B9_10 "汇流排9最大允许充电电流";
CM_ SG_ 2336157338 M2P_PermitMaxDisCharge_I_B9_10 "汇流排9最大允许放电电流";
CM_ SG_ 2336157339 M2P_Measure_Vol_B9_11 "汇流排9所有高压在线电柜外侧电压平均值    ";
CM_ SG_ 2336157339 M2P_Current_B9_11 "汇流排9所有电柜电流累加和";
CM_ SG_ 2336157339 M2P_PermitMaxCharge_I_B9_11 "汇流排9最大允许充电电流";
CM_ SG_ 2336157339 M2P_PermitMaxDisCharge_I_B9_11 "汇流排9最大允许放电电流";
CM_ SG_ 2336157340 M2P_Measure_Vol_B9_12 "汇流排9所有高压在线电柜外侧电压平均值    ";
CM_ SG_ 2336157340 M2P_Current_B9_12 "汇流排9所有电柜电流累加和";
CM_ SG_ 2336157340 M2P_PermitMaxCharge_I_B9_12 "汇流排9最大允许充电电流";
CM_ SG_ 2336157340 M2P_PermitMaxDisCharge_I_B9_12 "汇流排9最大允许放电电流";
CM_ SG_ 2336157341 M2P_Measure_Vol_B9_13 "汇流排9所有高压在线电柜外侧电压平均值    ";
CM_ SG_ 2336157341 M2P_Current_B9_13 "汇流排9所有电柜电流累加和";
CM_ SG_ 2336157341 M2P_PermitMaxCharge_I_B9_13 "汇流排9最大允许充电电流";
CM_ SG_ 2336157341 M2P_PermitMaxDisCharge_I_B9_13 "汇流排9最大允许放电电流";
CM_ SG_ 2336157342 M2P_Measure_Vol_B9_14 "汇流排9所有高压在线电柜外侧电压平均值    ";
CM_ SG_ 2336157342 M2P_Current_B9_14 "汇流排9所有电柜电流累加和";
CM_ SG_ 2336157342 M2P_PermitMaxCharge_I_B9_14 "汇流排9最大允许充电电流";
CM_ SG_ 2336157342 M2P_PermitMaxDisCharge_I_B9_14 "汇流排9最大允许放电电流";
CM_ SG_ 2336157343 M2P_Measure_Vol_B9_15 "汇流排9所有高压在线电柜外侧电压平均值    ";
CM_ SG_ 2336157343 M2P_Current_B9_15 "汇流排9所有电柜电流累加和";
CM_ SG_ 2336157343 M2P_PermitMaxCharge_I_B9_15 "汇流排9最大允许充电电流";
CM_ SG_ 2336157343 M2P_PermitMaxDisCharge_I_B9_15 "汇流排9最大允许放电电流";
CM_ SG_ 2336157344 M2P_Measure_Vol_B9_16 "汇流排9所有高压在线电柜外侧电压平均值    ";
CM_ SG_ 2336157344 M2P_Current_B9_16 "汇流排9所有电柜电流累加和";
CM_ SG_ 2336157344 M2P_PermitMaxCharge_I_B9_16 "汇流排9最大允许充电电流";
CM_ SG_ 2336157344 M2P_PermitMaxDisCharge_I_B9_16 "汇流排9最大允许放电电流";
CM_ SG_ 2336157345 M2P_Measure_Vol_B9_17 "汇流排9所有高压在线电柜外侧电压平均值    ";
CM_ SG_ 2336157345 M2P_Current_B9_17 "汇流排9所有电柜电流累加和";
CM_ SG_ 2336157345 M2P_PermitMaxCharge_I_B9_17 "汇流排9最大允许充电电流";
CM_ SG_ 2336157345 M2P_PermitMaxDisCharge_I_B9_17 "汇流排9最大允许放电电流";
CM_ SG_ 2336157346 M2P_Measure_Vol_B9_18 "汇流排9所有高压在线电柜外侧电压平均值    ";
CM_ SG_ 2336157346 M2P_Current_B9_18 "汇流排9所有电柜电流累加和";
CM_ SG_ 2336157346 M2P_PermitMaxCharge_I_B9_18 "汇流排9最大允许充电电流";
CM_ SG_ 2336157346 M2P_PermitMaxDisCharge_I_B9_18 "汇流排9最大允许放电电流";
CM_ SG_ 2336157347 M2P_Measure_Vol_B9_19 "汇流排9所有高压在线电柜外侧电压平均值    ";
CM_ SG_ 2336157347 M2P_Current_B9_19 "汇流排9所有电柜电流累加和";
CM_ SG_ 2336157347 M2P_PermitMaxCharge_I_B9_19 "汇流排9最大允许充电电流";
CM_ SG_ 2336157347 M2P_PermitMaxDisCharge_I_B9_19 "汇流排9最大允许放电电流";
CM_ SG_ 2336157348 M2P_Measure_Vol_B9_20 "汇流排9所有高压在线电柜外侧电压平均值    ";
CM_ SG_ 2336157348 M2P_Current_B9_20 "汇流排9所有电柜电流累加和";
CM_ SG_ 2336157348 M2P_PermitMaxCharge_I_B9_20 "汇流排9最大允许充电电流";
CM_ SG_ 2336157348 M2P_PermitMaxDisCharge_I_B9_20 "汇流排9最大允许放电电流";
CM_ SG_ 2336157349 M2P_Measure_Vol_B9_21 "汇流排9所有高压在线电柜外侧电压平均值    ";
CM_ SG_ 2336157349 M2P_Current_B9_21 "汇流排9所有电柜电流累加和";
CM_ SG_ 2336157349 M2P_PermitMaxCharge_I_B9_21 "汇流排9最大允许充电电流";
CM_ SG_ 2336157349 M2P_PermitMaxDisCharge_I_B9_21 "汇流排9最大允许放电电流";
CM_ SG_ 2336157350 M2P_Measure_Vol_B9_22 "汇流排9所有高压在线电柜外侧电压平均值    ";
CM_ SG_ 2336157350 M2P_Current_B9_22 "汇流排9所有电柜电流累加和";
CM_ SG_ 2336157350 M2P_PermitMaxCharge_I_B9_22 "汇流排9最大允许充电电流";
CM_ SG_ 2336157350 M2P_PermitMaxDisCharge_I_B9_22 "汇流排9最大允许放电电流";
CM_ SG_ 2336157351 M2P_Measure_Vol_B9_23 "汇流排9所有高压在线电柜外侧电压平均值    ";
CM_ SG_ 2336157351 M2P_Current_B9_23 "汇流排9所有电柜电流累加和";
CM_ SG_ 2336157351 M2P_PermitMaxCharge_I_B9_23 "汇流排9最大允许充电电流";
CM_ SG_ 2336157351 M2P_PermitMaxDisCharge_I_B9_23 "汇流排9最大允许放电电流";
CM_ SG_ 2336157352 M2P_Measure_Vol_B9_24 "汇流排9所有高压在线电柜外侧电压平均值    ";
CM_ SG_ 2336157352 M2P_Current_B9_24 "汇流排9所有电柜电流累加和";
CM_ SG_ 2336157352 M2P_PermitMaxCharge_I_B9_24 "汇流排9最大允许充电电流";
CM_ SG_ 2336157352 M2P_PermitMaxDisCharge_I_B9_24 "汇流排9最大允许放电电流";
CM_ SG_ 2336157353 M2P_Measure_Vol_B9_25 "汇流排9所有高压在线电柜外侧电压平均值    ";
CM_ SG_ 2336157353 M2P_Current_B9_25 "汇流排9所有电柜电流累加和";
CM_ SG_ 2336157353 M2P_PermitMaxCharge_I_B9_25 "汇流排9最大允许充电电流";
CM_ SG_ 2336157353 M2P_PermitMaxDisCharge_I_B9_25 "汇流排9最大允许放电电流";
CM_ SG_ 2336157354 M2P_Measure_Vol_B9_26 "汇流排9所有高压在线电柜外侧电压平均值    ";
CM_ SG_ 2336157354 M2P_Current_B9_26 "汇流排9所有电柜电流累加和";
CM_ SG_ 2336157354 M2P_PermitMaxCharge_I_B9_26 "汇流排9最大允许充电电流";
CM_ SG_ 2336157354 M2P_PermitMaxDisCharge_I_B9_26 "汇流排9最大允许放电电流";
CM_ SG_ 2336157355 M2P_Measure_Vol_B9_27 "汇流排9所有高压在线电柜外侧电压平均值    ";
CM_ SG_ 2336157355 M2P_Current_B9_27 "汇流排9所有电柜电流累加和";
CM_ SG_ 2336157355 M2P_PermitMaxCharge_I_B9_27 "汇流排9最大允许充电电流";
CM_ SG_ 2336157355 M2P_PermitMaxDisCharge_I_B9_27 "汇流排9最大允许放电电流";
CM_ SG_ 2336157356 M2P_Measure_Vol_B9_28 "汇流排9所有高压在线电柜外侧电压平均值    ";
CM_ SG_ 2336157356 M2P_Current_B9_28 "汇流排9所有电柜电流累加和";
CM_ SG_ 2336157356 M2P_PermitMaxCharge_I_B9_28 "汇流排9最大允许充电电流";
CM_ SG_ 2336157356 M2P_PermitMaxDisCharge_I_B9_28 "汇流排9最大允许放电电流";
CM_ SG_ 2336157357 M2P_Measure_Vol_B9_29 "汇流排9所有高压在线电柜外侧电压平均值    ";
CM_ SG_ 2336157357 M2P_Current_B9_29 "汇流排9所有电柜电流累加和";
CM_ SG_ 2336157357 M2P_PermitMaxCharge_I_B9_29 "汇流排9最大允许充电电流";
CM_ SG_ 2336157357 M2P_PermitMaxDisCharge_I_B9_29 "汇流排9最大允许放电电流";
CM_ SG_ 2336157358 M2P_Measure_Vol_B9_30 "汇流排9所有高压在线电柜外侧电压平均值    ";
CM_ SG_ 2336157358 M2P_Current_B9_30 "汇流排9所有电柜电流累加和";
CM_ SG_ 2336157358 M2P_PermitMaxCharge_I_B9_30 "汇流排9最大允许充电电流";
CM_ SG_ 2336157358 M2P_PermitMaxDisCharge_I_B9_30 "汇流排9最大允许放电电流";
CM_ SG_ 2336157359 M2P_Measure_Vol_B9_31 "汇流排9所有高压在线电柜外侧电压平均值    ";
CM_ SG_ 2336157359 M2P_Current_B9_31 "汇流排9所有电柜电流累加和";
CM_ SG_ 2336157359 M2P_PermitMaxCharge_I_B9_31 "汇流排9最大允许充电电流";
CM_ SG_ 2336157359 M2P_PermitMaxDisCharge_I_B9_31 "汇流排9最大允许放电电流";
CM_ SG_ 2336222865 M2P_PermitMaxVolt_B9_01 "汇流排9最高允许充电电压 （配置量）";
CM_ SG_ 2336222865 M2P_PermitMinVolt_B9_01 "汇流排9最低允许放电电压 （配置量）";
CM_ SG_ 2336222865 M2P_PermitMaxPow_Chg_B9_01 "汇流排9最大允许充电功率";
CM_ SG_ 2336222865 M2P_PermitMaxPow_DisChg_B9_01 "汇流排9最大允许放电功率";
CM_ SG_ 2336222866 M2P_PermitMaxVolt_B9_02 "汇流排9最高允许充电电压 （配置量）";
CM_ SG_ 2336222866 M2P_PermitMinVolt_B9_02 "汇流排9最低允许放电电压 （配置量）";
CM_ SG_ 2336222866 M2P_PermitMaxPow_Chg_B9_02 "汇流排9最大允许充电功率";
CM_ SG_ 2336222866 M2P_PermitMaxPow_DisChg_B9_02 "汇流排9最大允许放电功率";
CM_ SG_ 2336222867 M2P_PermitMaxVolt_B9_03 "汇流排9最高允许充电电压 （配置量）";
CM_ SG_ 2336222867 M2P_PermitMinVolt_B9_03 "汇流排9最低允许放电电压 （配置量）";
CM_ SG_ 2336222867 M2P_PermitMaxPow_Chg_B9_03 "汇流排9最大允许充电功率";
CM_ SG_ 2336222867 M2P_PermitMaxPow_DisChg_B9_03 "汇流排9最大允许放电功率";
CM_ SG_ 2336222868 M2P_PermitMaxVolt_B9_04 "汇流排9最高允许充电电压 （配置量）";
CM_ SG_ 2336222868 M2P_PermitMinVolt_B9_04 "汇流排9最低允许放电电压 （配置量）";
CM_ SG_ 2336222868 M2P_PermitMaxPow_Chg_B9_04 "汇流排9最大允许充电功率";
CM_ SG_ 2336222868 M2P_PermitMaxPow_DisChg_B9_04 "汇流排9最大允许放电功率";
CM_ SG_ 2336222869 M2P_PermitMaxVolt_B9_05 "汇流排9最高允许充电电压 （配置量）";
CM_ SG_ 2336222869 M2P_PermitMinVolt_B9_05 "汇流排9最低允许放电电压 （配置量）";
CM_ SG_ 2336222869 M2P_PermitMaxPow_Chg_B9_05 "汇流排9最大允许充电功率";
CM_ SG_ 2336222869 M2P_PermitMaxPow_DisChg_B9_05 "汇流排9最大允许放电功率";
CM_ SG_ 2336222870 M2P_PermitMaxVolt_B9_06 "汇流排9最高允许充电电压 （配置量）";
CM_ SG_ 2336222870 M2P_PermitMinVolt_B9_06 "汇流排9最低允许放电电压 （配置量）";
CM_ SG_ 2336222870 M2P_PermitMaxPow_Chg_B9_06 "汇流排9最大允许充电功率";
CM_ SG_ 2336222870 M2P_PermitMaxPow_DisChg_B9_06 "汇流排9最大允许放电功率";
CM_ SG_ 2336222871 M2P_PermitMaxVolt_B9_07 "汇流排9最高允许充电电压 （配置量）";
CM_ SG_ 2336222871 M2P_PermitMinVolt_B9_07 "汇流排9最低允许放电电压 （配置量）";
CM_ SG_ 2336222871 M2P_PermitMaxPow_Chg_B9_07 "汇流排9最大允许充电功率";
CM_ SG_ 2336222871 M2P_PermitMaxPow_DisChg_B9_07 "汇流排9最大允许放电功率";
CM_ SG_ 2336222872 M2P_PermitMaxVolt_B9_08 "汇流排9最高允许充电电压 （配置量）";
CM_ SG_ 2336222872 M2P_PermitMinVolt_B9_08 "汇流排9最低允许放电电压 （配置量）";
CM_ SG_ 2336222872 M2P_PermitMaxPow_Chg_B9_08 "汇流排9最大允许充电功率";
CM_ SG_ 2336222872 M2P_PermitMaxPow_DisChg_B9_08 "汇流排9最大允许放电功率";
CM_ SG_ 2336222873 M2P_PermitMaxVolt_B9_09 "汇流排9最高允许充电电压 （配置量）";
CM_ SG_ 2336222873 M2P_PermitMinVolt_B9_09 "汇流排9最低允许放电电压 （配置量）";
CM_ SG_ 2336222873 M2P_PermitMaxPow_Chg_B9_09 "汇流排9最大允许充电功率";
CM_ SG_ 2336222873 M2P_PermitMaxPow_DisChg_B9_09 "汇流排9最大允许放电功率";
CM_ SG_ 2336222874 M2P_PermitMaxVolt_B9_10 "汇流排9最高允许充电电压 （配置量）";
CM_ SG_ 2336222874 M2P_PermitMinVolt_B9_10 "汇流排9最低允许放电电压 （配置量）";
CM_ SG_ 2336222874 M2P_PermitMaxPow_Chg_B9_10 "汇流排9最大允许充电功率";
CM_ SG_ 2336222874 M2P_PermitMaxPow_DisChg_B9_10 "汇流排9最大允许放电功率";
CM_ SG_ 2336222875 M2P_PermitMaxVolt_B9_11 "汇流排9最高允许充电电压 （配置量）";
CM_ SG_ 2336222875 M2P_PermitMinVolt_B9_11 "汇流排9最低允许放电电压 （配置量）";
CM_ SG_ 2336222875 M2P_PermitMaxPow_Chg_B9_11 "汇流排9最大允许充电功率";
CM_ SG_ 2336222875 M2P_PermitMaxPow_DisChg_B9_11 "汇流排9最大允许放电功率";
CM_ SG_ 2336222876 M2P_PermitMaxVolt_B9_12 "汇流排9最高允许充电电压 （配置量）";
CM_ SG_ 2336222876 M2P_PermitMinVolt_B9_12 "汇流排9最低允许放电电压 （配置量）";
CM_ SG_ 2336222876 M2P_PermitMaxPow_Chg_B9_12 "汇流排9最大允许充电功率";
CM_ SG_ 2336222876 M2P_PermitMaxPow_DisChg_B9_12 "汇流排9最大允许放电功率";
CM_ SG_ 2336222877 M2P_PermitMaxVolt_B9_13 "汇流排9最高允许充电电压 （配置量）";
CM_ SG_ 2336222877 M2P_PermitMinVolt_B9_13 "汇流排9最低允许放电电压 （配置量）";
CM_ SG_ 2336222877 M2P_PermitMaxPow_Chg_B9_13 "汇流排9最大允许充电功率";
CM_ SG_ 2336222877 M2P_PermitMaxPow_DisChg_B9_13 "汇流排9最大允许放电功率";
CM_ SG_ 2336222878 M2P_PermitMaxVolt_B9_14 "汇流排9最高允许充电电压 （配置量）";
CM_ SG_ 2336222878 M2P_PermitMinVolt_B9_14 "汇流排9最低允许放电电压 （配置量）";
CM_ SG_ 2336222878 M2P_PermitMaxPow_Chg_B9_14 "汇流排9最大允许充电功率";
CM_ SG_ 2336222878 M2P_PermitMaxPow_DisChg_B9_14 "汇流排9最大允许放电功率";
CM_ SG_ 2336222879 M2P_PermitMaxVolt_B9_15 "汇流排9最高允许充电电压 （配置量）";
CM_ SG_ 2336222879 M2P_PermitMinVolt_B9_15 "汇流排9最低允许放电电压 （配置量）";
CM_ SG_ 2336222879 M2P_PermitMaxPow_Chg_B9_15 "汇流排9最大允许充电功率";
CM_ SG_ 2336222879 M2P_PermitMaxPow_DisChg_B9_15 "汇流排9最大允许放电功率";
CM_ SG_ 2336222880 M2P_PermitMaxVolt_B9_16 "汇流排9最高允许充电电压 （配置量）";
CM_ SG_ 2336222880 M2P_PermitMinVolt_B9_16 "汇流排9最低允许放电电压 （配置量）";
CM_ SG_ 2336222880 M2P_PermitMaxPow_Chg_B9_16 "汇流排9最大允许充电功率";
CM_ SG_ 2336222880 M2P_PermitMaxPow_DisChg_B9_16 "汇流排9最大允许放电功率";
CM_ SG_ 2336222881 M2P_PermitMaxVolt_B9_17 "汇流排9最高允许充电电压 （配置量）";
CM_ SG_ 2336222881 M2P_PermitMinVolt_B9_17 "汇流排9最低允许放电电压 （配置量）";
CM_ SG_ 2336222881 M2P_PermitMaxPow_Chg_B9_17 "汇流排9最大允许充电功率";
CM_ SG_ 2336222881 M2P_PermitMaxPow_DisChg_B9_17 "汇流排9最大允许放电功率";
CM_ SG_ 2336222882 M2P_PermitMaxVolt_B9_18 "汇流排9最高允许充电电压 （配置量）";
CM_ SG_ 2336222882 M2P_PermitMinVolt_B9_18 "汇流排9最低允许放电电压 （配置量）";
CM_ SG_ 2336222882 M2P_PermitMaxPow_Chg_B9_18 "汇流排9最大允许充电功率";
CM_ SG_ 2336222882 M2P_PermitMaxPow_DisChg_B9_18 "汇流排9最大允许放电功率";
CM_ SG_ 2336222883 M2P_PermitMaxVolt_B9_19 "汇流排9最高允许充电电压 （配置量）";
CM_ SG_ 2336222883 M2P_PermitMinVolt_B9_19 "汇流排9最低允许放电电压 （配置量）";
CM_ SG_ 2336222883 M2P_PermitMaxPow_Chg_B9_19 "汇流排9最大允许充电功率";
CM_ SG_ 2336222883 M2P_PermitMaxPow_DisChg_B9_19 "汇流排9最大允许放电功率";
CM_ SG_ 2336222884 M2P_PermitMaxVolt_B9_20 "汇流排9最高允许充电电压 （配置量）";
CM_ SG_ 2336222884 M2P_PermitMinVolt_B9_20 "汇流排9最低允许放电电压 （配置量）";
CM_ SG_ 2336222884 M2P_PermitMaxPow_Chg_B9_20 "汇流排9最大允许充电功率";
CM_ SG_ 2336222884 M2P_PermitMaxPow_DisChg_B9_20 "汇流排9最大允许放电功率";
CM_ SG_ 2336222885 M2P_PermitMaxVolt_B9_21 "汇流排9最高允许充电电压 （配置量）";
CM_ SG_ 2336222885 M2P_PermitMinVolt_B9_21 "汇流排9最低允许放电电压 （配置量）";
CM_ SG_ 2336222885 M2P_PermitMaxPow_Chg_B9_21 "汇流排9最大允许充电功率";
CM_ SG_ 2336222885 M2P_PermitMaxPow_DisChg_B9_21 "汇流排9最大允许放电功率";
CM_ SG_ 2336222886 M2P_PermitMaxVolt_B9_22 "汇流排9最高允许充电电压 （配置量）";
CM_ SG_ 2336222886 M2P_PermitMinVolt_B9_22 "汇流排9最低允许放电电压 （配置量）";
CM_ SG_ 2336222886 M2P_PermitMaxPow_Chg_B9_22 "汇流排9最大允许充电功率";
CM_ SG_ 2336222886 M2P_PermitMaxPow_DisChg_B9_22 "汇流排9最大允许放电功率";
CM_ SG_ 2336222887 M2P_PermitMaxVolt_B9_23 "汇流排9最高允许充电电压 （配置量）";
CM_ SG_ 2336222887 M2P_PermitMinVolt_B9_23 "汇流排9最低允许放电电压 （配置量）";
CM_ SG_ 2336222887 M2P_PermitMaxPow_Chg_B9_23 "汇流排9最大允许充电功率";
CM_ SG_ 2336222887 M2P_PermitMaxPow_DisChg_B9_23 "汇流排9最大允许放电功率";
CM_ SG_ 2336222888 M2P_PermitMaxVolt_B9_24 "汇流排9最高允许充电电压 （配置量）";
CM_ SG_ 2336222888 M2P_PermitMinVolt_B9_24 "汇流排9最低允许放电电压 （配置量）";
CM_ SG_ 2336222888 M2P_PermitMaxPow_Chg_B9_24 "汇流排9最大允许充电功率";
CM_ SG_ 2336222888 M2P_PermitMaxPow_DisChg_B9_24 "汇流排9最大允许放电功率";
CM_ SG_ 2336222889 M2P_PermitMaxVolt_B9_25 "汇流排9最高允许充电电压 （配置量）";
CM_ SG_ 2336222889 M2P_PermitMinVolt_B9_25 "汇流排9最低允许放电电压 （配置量）";
CM_ SG_ 2336222889 M2P_PermitMaxPow_Chg_B9_25 "汇流排9最大允许充电功率";
CM_ SG_ 2336222889 M2P_PermitMaxPow_DisChg_B9_25 "汇流排9最大允许放电功率";
CM_ SG_ 2336222890 M2P_PermitMaxVolt_B9_26 "汇流排9最高允许充电电压 （配置量）";
CM_ SG_ 2336222890 M2P_PermitMinVolt_B9_26 "汇流排9最低允许放电电压 （配置量）";
CM_ SG_ 2336222890 M2P_PermitMaxPow_Chg_B9_26 "汇流排9最大允许充电功率";
CM_ SG_ 2336222890 M2P_PermitMaxPow_DisChg_B9_26 "汇流排9最大允许放电功率";
CM_ SG_ 2336222891 M2P_PermitMaxVolt_B9_27 "汇流排9最高允许充电电压 （配置量）";
CM_ SG_ 2336222891 M2P_PermitMinVolt_B9_27 "汇流排9最低允许放电电压 （配置量）";
CM_ SG_ 2336222891 M2P_PermitMaxPow_Chg_B9_27 "汇流排9最大允许充电功率";
CM_ SG_ 2336222891 M2P_PermitMaxPow_DisChg_B9_27 "汇流排9最大允许放电功率";
CM_ SG_ 2336222892 M2P_PermitMaxVolt_B9_28 "汇流排9最高允许充电电压 （配置量）";
CM_ SG_ 2336222892 M2P_PermitMinVolt_B9_28 "汇流排9最低允许放电电压 （配置量）";
CM_ SG_ 2336222892 M2P_PermitMaxPow_Chg_B9_28 "汇流排9最大允许充电功率";
CM_ SG_ 2336222892 M2P_PermitMaxPow_DisChg_B9_28 "汇流排9最大允许放电功率";
CM_ SG_ 2336222893 M2P_PermitMaxVolt_B9_29 "汇流排9最高允许充电电压 （配置量）";
CM_ SG_ 2336222893 M2P_PermitMinVolt_B9_29 "汇流排9最低允许放电电压 （配置量）";
CM_ SG_ 2336222893 M2P_PermitMaxPow_Chg_B9_29 "汇流排9最大允许充电功率";
CM_ SG_ 2336222893 M2P_PermitMaxPow_DisChg_B9_29 "汇流排9最大允许放电功率";
CM_ SG_ 2336222894 M2P_PermitMaxVolt_B9_30 "汇流排9最高允许充电电压 （配置量）";
CM_ SG_ 2336222894 M2P_PermitMinVolt_B9_30 "汇流排9最低允许放电电压 （配置量）";
CM_ SG_ 2336222894 M2P_PermitMaxPow_Chg_B9_30 "汇流排9最大允许充电功率";
CM_ SG_ 2336222894 M2P_PermitMaxPow_DisChg_B9_30 "汇流排9最大允许放电功率";
CM_ SG_ 2336222895 M2P_PermitMaxVolt_B9_31 "汇流排9最高允许充电电压 （配置量）";
CM_ SG_ 2336222895 M2P_PermitMinVolt_B9_31 "汇流排9最低允许放电电压 （配置量）";
CM_ SG_ 2336222895 M2P_PermitMaxPow_Chg_B9_31 "汇流排9最大允许充电功率";
CM_ SG_ 2336222895 M2P_PermitMaxPow_DisChg_B9_31 "汇流排9最大允许放电功率";
CM_ SG_ 2336288401 M2P_Power_B9_01 "汇流排9实时功率";
CM_ SG_ 2336288401 M2P_SysremEngy_Chg_B9_01 "汇流排9充电剩余能量";
CM_ SG_ 2336288401 M2P_SysremEngy_DisChg_B9_01 "汇流排9放电剩余能量";
CM_ SG_ 2336288401 M2P_SysMaxVolt_B9_01 "汇流排9单体最大电压  ";
CM_ SG_ 2336288402 M2P_Power_B9_02 "汇流排9实时功率";
CM_ SG_ 2336288402 M2P_SysremEngy_Chg_B9_02 "汇流排9充电剩余能量";
CM_ SG_ 2336288402 M2P_SysremEngy_DisChg_B9_02 "汇流排9放电剩余能量";
CM_ SG_ 2336288402 M2P_SysMaxVolt_B9_02 "汇流排9单体最大电压  ";
CM_ SG_ 2336288403 M2P_Power_B9_03 "汇流排9实时功率";
CM_ SG_ 2336288403 M2P_SysremEngy_Chg_B9_03 "汇流排9充电剩余能量";
CM_ SG_ 2336288403 M2P_SysremEngy_DisChg_B9_03 "汇流排9放电剩余能量";
CM_ SG_ 2336288403 M2P_SysMaxVolt_B9_03 "汇流排9单体最大电压  ";
CM_ SG_ 2336288404 M2P_Power_B9_04 "汇流排9实时功率";
CM_ SG_ 2336288404 M2P_SysremEngy_Chg_B9_04 "汇流排9充电剩余能量";
CM_ SG_ 2336288404 M2P_SysremEngy_DisChg_B9_04 "汇流排9放电剩余能量";
CM_ SG_ 2336288404 M2P_SysMaxVolt_B9_04 "汇流排9单体最大电压  ";
CM_ SG_ 2336288405 M2P_Power_B9_05 "汇流排9实时功率";
CM_ SG_ 2336288405 M2P_SysremEngy_Chg_B9_05 "汇流排9充电剩余能量";
CM_ SG_ 2336288405 M2P_SysremEngy_DisChg_B9_05 "汇流排9放电剩余能量";
CM_ SG_ 2336288405 M2P_SysMaxVolt_B9_05 "汇流排9单体最大电压  ";
CM_ SG_ 2336288406 M2P_Power_B9_06 "汇流排9实时功率";
CM_ SG_ 2336288406 M2P_SysremEngy_Chg_B9_06 "汇流排9充电剩余能量";
CM_ SG_ 2336288406 M2P_SysremEngy_DisChg_B9_06 "汇流排9放电剩余能量";
CM_ SG_ 2336288406 M2P_SysMaxVolt_B9_06 "汇流排9单体最大电压  ";
CM_ SG_ 2336288407 M2P_Power_B9_07 "汇流排9实时功率";
CM_ SG_ 2336288407 M2P_SysremEngy_Chg_B9_07 "汇流排9充电剩余能量";
CM_ SG_ 2336288407 M2P_SysremEngy_DisChg_B9_07 "汇流排9放电剩余能量";
CM_ SG_ 2336288407 M2P_SysMaxVolt_B9_07 "汇流排9单体最大电压  ";
CM_ SG_ 2336288408 M2P_Power_B9_08 "汇流排9实时功率";
CM_ SG_ 2336288408 M2P_SysremEngy_Chg_B9_08 "汇流排9充电剩余能量";
CM_ SG_ 2336288408 M2P_SysremEngy_DisChg_B9_08 "汇流排9放电剩余能量";
CM_ SG_ 2336288408 M2P_SysMaxVolt_B9_08 "汇流排9单体最大电压  ";
CM_ SG_ 2336288409 M2P_Power_B9_09 "汇流排9实时功率";
CM_ SG_ 2336288409 M2P_SysremEngy_Chg_B9_09 "汇流排9充电剩余能量";
CM_ SG_ 2336288409 M2P_SysremEngy_DisChg_B9_09 "汇流排9放电剩余能量";
CM_ SG_ 2336288409 M2P_SysMaxVolt_B9_09 "汇流排9单体最大电压  ";
CM_ SG_ 2336288410 M2P_Power_B9_10 "汇流排9实时功率";
CM_ SG_ 2336288410 M2P_SysremEngy_Chg_B9_10 "汇流排9充电剩余能量";
CM_ SG_ 2336288410 M2P_SysremEngy_DisChg_B9_10 "汇流排9放电剩余能量";
CM_ SG_ 2336288410 M2P_SysMaxVolt_B9_10 "汇流排9单体最大电压  ";
CM_ SG_ 2336288411 M2P_Power_B9_11 "汇流排9实时功率";
CM_ SG_ 2336288411 M2P_SysremEngy_Chg_B9_11 "汇流排9充电剩余能量";
CM_ SG_ 2336288411 M2P_SysremEngy_DisChg_B9_11 "汇流排9放电剩余能量";
CM_ SG_ 2336288411 M2P_SysMaxVolt_B9_11 "汇流排9单体最大电压  ";
CM_ SG_ 2336288412 M2P_Power_B9_12 "汇流排9实时功率";
CM_ SG_ 2336288412 M2P_SysremEngy_Chg_B9_12 "汇流排9充电剩余能量";
CM_ SG_ 2336288412 M2P_SysremEngy_DisChg_B9_12 "汇流排9放电剩余能量";
CM_ SG_ 2336288412 M2P_SysMaxVolt_B9_12 "汇流排9单体最大电压  ";
CM_ SG_ 2336288413 M2P_Power_B9_13 "汇流排9实时功率";
CM_ SG_ 2336288413 M2P_SysremEngy_Chg_B9_13 "汇流排9充电剩余能量";
CM_ SG_ 2336288413 M2P_SysremEngy_DisChg_B9_13 "汇流排9放电剩余能量";
CM_ SG_ 2336288413 M2P_SysMaxVolt_B9_13 "汇流排9单体最大电压  ";
CM_ SG_ 2336288414 M2P_Power_B9_14 "汇流排9实时功率";
CM_ SG_ 2336288414 M2P_SysremEngy_Chg_B9_14 "汇流排9充电剩余能量";
CM_ SG_ 2336288414 M2P_SysremEngy_DisChg_B9_14 "汇流排9放电剩余能量";
CM_ SG_ 2336288414 M2P_SysMaxVolt_B9_14 "汇流排9单体最大电压  ";
CM_ SG_ 2336288415 M2P_Power_B9_15 "汇流排9实时功率";
CM_ SG_ 2336288415 M2P_SysremEngy_Chg_B9_15 "汇流排9充电剩余能量";
CM_ SG_ 2336288415 M2P_SysremEngy_DisChg_B9_15 "汇流排9放电剩余能量";
CM_ SG_ 2336288415 M2P_SysMaxVolt_B9_15 "汇流排9单体最大电压  ";
CM_ SG_ 2336288416 M2P_Power_B9_16 "汇流排9实时功率";
CM_ SG_ 2336288416 M2P_SysremEngy_Chg_B9_16 "汇流排9充电剩余能量";
CM_ SG_ 2336288416 M2P_SysremEngy_DisChg_B9_16 "汇流排9放电剩余能量";
CM_ SG_ 2336288416 M2P_SysMaxVolt_B9_16 "汇流排9单体最大电压  ";
CM_ SG_ 2336288417 M2P_Power_B9_17 "汇流排9实时功率";
CM_ SG_ 2336288417 M2P_SysremEngy_Chg_B9_17 "汇流排9充电剩余能量";
CM_ SG_ 2336288417 M2P_SysremEngy_DisChg_B9_17 "汇流排9放电剩余能量";
CM_ SG_ 2336288417 M2P_SysMaxVolt_B9_17 "汇流排9单体最大电压  ";
CM_ SG_ 2336288418 M2P_Power_B9_18 "汇流排9实时功率";
CM_ SG_ 2336288418 M2P_SysremEngy_Chg_B9_18 "汇流排9充电剩余能量";
CM_ SG_ 2336288418 M2P_SysremEngy_DisChg_B9_18 "汇流排9放电剩余能量";
CM_ SG_ 2336288418 M2P_SysMaxVolt_B9_18 "汇流排9单体最大电压  ";
CM_ SG_ 2336288419 M2P_Power_B9_19 "汇流排9实时功率";
CM_ SG_ 2336288419 M2P_SysremEngy_Chg_B9_19 "汇流排9充电剩余能量";
CM_ SG_ 2336288419 M2P_SysremEngy_DisChg_B9_19 "汇流排9放电剩余能量";
CM_ SG_ 2336288419 M2P_SysMaxVolt_B9_19 "汇流排9单体最大电压  ";
CM_ SG_ 2336288420 M2P_Power_B9_20 "汇流排9实时功率";
CM_ SG_ 2336288420 M2P_SysremEngy_Chg_B9_20 "汇流排9充电剩余能量";
CM_ SG_ 2336288420 M2P_SysremEngy_DisChg_B9_20 "汇流排9放电剩余能量";
CM_ SG_ 2336288420 M2P_SysMaxVolt_B9_20 "汇流排9单体最大电压  ";
CM_ SG_ 2336288421 M2P_Power_B9_21 "汇流排9实时功率";
CM_ SG_ 2336288421 M2P_SysremEngy_Chg_B9_21 "汇流排9充电剩余能量";
CM_ SG_ 2336288421 M2P_SysremEngy_DisChg_B9_21 "汇流排9放电剩余能量";
CM_ SG_ 2336288421 M2P_SysMaxVolt_B9_21 "汇流排9单体最大电压  ";
CM_ SG_ 2336288422 M2P_Power_B9_22 "汇流排9实时功率";
CM_ SG_ 2336288422 M2P_SysremEngy_Chg_B9_22 "汇流排9充电剩余能量";
CM_ SG_ 2336288422 M2P_SysremEngy_DisChg_B9_22 "汇流排9放电剩余能量";
CM_ SG_ 2336288422 M2P_SysMaxVolt_B9_22 "汇流排9单体最大电压  ";
CM_ SG_ 2336288423 M2P_Power_B9_23 "汇流排9实时功率";
CM_ SG_ 2336288423 M2P_SysremEngy_Chg_B9_23 "汇流排9充电剩余能量";
CM_ SG_ 2336288423 M2P_SysremEngy_DisChg_B9_23 "汇流排9放电剩余能量";
CM_ SG_ 2336288423 M2P_SysMaxVolt_B9_23 "汇流排9单体最大电压  ";
CM_ SG_ 2336288424 M2P_Power_B9_24 "汇流排9实时功率";
CM_ SG_ 2336288424 M2P_SysremEngy_Chg_B9_24 "汇流排9充电剩余能量";
CM_ SG_ 2336288424 M2P_SysremEngy_DisChg_B9_24 "汇流排9放电剩余能量";
CM_ SG_ 2336288424 M2P_SysMaxVolt_B9_24 "汇流排9单体最大电压  ";
CM_ SG_ 2336288425 M2P_Power_B9_25 "汇流排9实时功率";
CM_ SG_ 2336288425 M2P_SysremEngy_Chg_B9_25 "汇流排9充电剩余能量";
CM_ SG_ 2336288425 M2P_SysremEngy_DisChg_B9_25 "汇流排9放电剩余能量";
CM_ SG_ 2336288425 M2P_SysMaxVolt_B9_25 "汇流排9单体最大电压  ";
CM_ SG_ 2336288426 M2P_Power_B9_26 "汇流排9实时功率";
CM_ SG_ 2336288426 M2P_SysremEngy_Chg_B9_26 "汇流排9充电剩余能量";
CM_ SG_ 2336288426 M2P_SysremEngy_DisChg_B9_26 "汇流排9放电剩余能量";
CM_ SG_ 2336288426 M2P_SysMaxVolt_B9_26 "汇流排9单体最大电压  ";
CM_ SG_ 2336288427 M2P_Power_B9_27 "汇流排9实时功率";
CM_ SG_ 2336288427 M2P_SysremEngy_Chg_B9_27 "汇流排9充电剩余能量";
CM_ SG_ 2336288427 M2P_SysremEngy_DisChg_B9_27 "汇流排9放电剩余能量";
CM_ SG_ 2336288427 M2P_SysMaxVolt_B9_27 "汇流排9单体最大电压  ";
CM_ SG_ 2336288428 M2P_Power_B9_28 "汇流排9实时功率";
CM_ SG_ 2336288428 M2P_SysremEngy_Chg_B9_28 "汇流排9充电剩余能量";
CM_ SG_ 2336288428 M2P_SysremEngy_DisChg_B9_28 "汇流排9放电剩余能量";
CM_ SG_ 2336288428 M2P_SysMaxVolt_B9_28 "汇流排9单体最大电压  ";
CM_ SG_ 2336288429 M2P_Power_B9_29 "汇流排9实时功率";
CM_ SG_ 2336288429 M2P_SysremEngy_Chg_B9_29 "汇流排9充电剩余能量";
CM_ SG_ 2336288429 M2P_SysremEngy_DisChg_B9_29 "汇流排9放电剩余能量";
CM_ SG_ 2336288429 M2P_SysMaxVolt_B9_29 "汇流排9单体最大电压  ";
CM_ SG_ 2336288430 M2P_Power_B9_30 "汇流排9实时功率";
CM_ SG_ 2336288430 M2P_SysremEngy_Chg_B9_30 "汇流排9充电剩余能量";
CM_ SG_ 2336288430 M2P_SysremEngy_DisChg_B9_30 "汇流排9放电剩余能量";
CM_ SG_ 2336288430 M2P_SysMaxVolt_B9_30 "汇流排9单体最大电压  ";
CM_ SG_ 2336288431 M2P_Power_B9_31 "汇流排9实时功率";
CM_ SG_ 2336288431 M2P_SysremEngy_Chg_B9_31 "汇流排9充电剩余能量";
CM_ SG_ 2336288431 M2P_SysremEngy_DisChg_B9_31 "汇流排9放电剩余能量";
CM_ SG_ 2336288431 M2P_SysMaxVolt_B9_31 "汇流排9单体最大电压  ";
CM_ SG_ 2336353937 M2P_SysMinVolt_B9_01 "汇流排9单体最小电压";
CM_ SG_ 2336353937 M2P_SysAvgVolt_B9_01 "汇流排9单体平均电压";
CM_ SG_ 2336353937 M2P_BMS_Status_B9 "汇流排9能量状态";
CM_ SG_ 2336353937 M2P_SOC_B9 "汇流排9系统SOC";
CM_ SG_ 2336353937 M2P_SOH_B9 "汇流排9系统SOH";
CM_ SG_ 2336353937 Reserved_01 "预留";
CM_ SG_ 2336353938 M2P_SysMinVolt_B9_02 "汇流排9单体最小电压";
CM_ SG_ 2336353938 M2P_SysAvgVolt_B9_02 "汇流排9单体平均电压";
CM_ SG_ 2336353938 M2P_BMS_Status_B9 "汇流排9能量状态";
CM_ SG_ 2336353938 M2P_SOC_B9 "汇流排9系统SOC";
CM_ SG_ 2336353938 M2P_SOH_B9 "汇流排9系统SOH";
CM_ SG_ 2336353938 Reserved_02 "预留";
CM_ SG_ 2336353939 M2P_SysMinVolt_B9_03 "汇流排9单体最小电压";
CM_ SG_ 2336353939 M2P_SysAvgVolt_B9_03 "汇流排9单体平均电压";
CM_ SG_ 2336353939 M2P_BMS_Status_B9 "汇流排9能量状态";
CM_ SG_ 2336353939 M2P_SOC_B9 "汇流排9系统SOC";
CM_ SG_ 2336353939 M2P_SOH_B9 "汇流排9系统SOH";
CM_ SG_ 2336353939 Reserved_03 "预留";
CM_ SG_ 2336353940 M2P_SysMinVolt_B9_04 "汇流排9单体最小电压";
CM_ SG_ 2336353940 M2P_SysAvgVolt_B9_04 "汇流排9单体平均电压";
CM_ SG_ 2336353940 M2P_BMS_Status_B9 "汇流排9能量状态";
CM_ SG_ 2336353940 M2P_SOC_B9 "汇流排9系统SOC";
CM_ SG_ 2336353940 M2P_SOH_B9 "汇流排9系统SOH";
CM_ SG_ 2336353940 Reserved_04 "预留";
CM_ SG_ 2336353941 M2P_SysMinVolt_B9_05 "汇流排9单体最小电压";
CM_ SG_ 2336353941 M2P_SysAvgVolt_B9_05 "汇流排9单体平均电压";
CM_ SG_ 2336353941 M2P_BMS_Status_B9 "汇流排9能量状态";
CM_ SG_ 2336353941 M2P_SOC_B9 "汇流排9系统SOC";
CM_ SG_ 2336353941 M2P_SOH_B9 "汇流排9系统SOH";
CM_ SG_ 2336353941 Reserved_05 "预留";
CM_ SG_ 2336353942 M2P_SysMinVolt_B9_06 "汇流排9单体最小电压";
CM_ SG_ 2336353942 M2P_SysAvgVolt_B9_06 "汇流排9单体平均电压";
CM_ SG_ 2336353942 M2P_BMS_Status_B9 "汇流排9能量状态";
CM_ SG_ 2336353942 M2P_SOC_B9 "汇流排9系统SOC";
CM_ SG_ 2336353942 M2P_SOH_B9 "汇流排9系统SOH";
CM_ SG_ 2336353942 Reserved_06 "预留";
CM_ SG_ 2336353943 M2P_SysMinVolt_B9_07 "汇流排9单体最小电压";
CM_ SG_ 2336353943 M2P_SysAvgVolt_B9_07 "汇流排9单体平均电压";
CM_ SG_ 2336353943 M2P_BMS_Status_B9 "汇流排9能量状态";
CM_ SG_ 2336353943 M2P_SOC_B9 "汇流排9系统SOC";
CM_ SG_ 2336353943 M2P_SOH_B9 "汇流排9系统SOH";
CM_ SG_ 2336353943 Reserved_07 "预留";
CM_ SG_ 2336353944 M2P_SysMinVolt_B9_08 "汇流排9单体最小电压";
CM_ SG_ 2336353944 M2P_SysAvgVolt_B9_08 "汇流排9单体平均电压";
CM_ SG_ 2336353944 M2P_BMS_Status_B9 "汇流排9能量状态";
CM_ SG_ 2336353944 M2P_SOC_B9 "汇流排9系统SOC";
CM_ SG_ 2336353944 M2P_SOH_B9 "汇流排9系统SOH";
CM_ SG_ 2336353944 Reserved_08 "预留";
CM_ SG_ 2336353945 M2P_SysMinVolt_B9_09 "汇流排9单体最小电压";
CM_ SG_ 2336353945 M2P_SysAvgVolt_B9_09 "汇流排9单体平均电压";
CM_ SG_ 2336353945 M2P_BMS_Status_B9 "汇流排9能量状态";
CM_ SG_ 2336353945 M2P_SOC_B9 "汇流排9系统SOC";
CM_ SG_ 2336353945 M2P_SOH_B9 "汇流排9系统SOH";
CM_ SG_ 2336353945 Reserved_09 "预留";
CM_ SG_ 2336353946 M2P_SysMinVolt_B9_10 "汇流排9单体最小电压";
CM_ SG_ 2336353946 M2P_SysAvgVolt_B9_10 "汇流排9单体平均电压";
CM_ SG_ 2336353946 M2P_BMS_Status_B9 "汇流排9能量状态";
CM_ SG_ 2336353946 M2P_SOC_B9 "汇流排9系统SOC";
CM_ SG_ 2336353946 M2P_SOH_B9 "汇流排9系统SOH";
CM_ SG_ 2336353946 Reserved_10 "预留";
CM_ SG_ 2336353947 M2P_SysMinVolt_B9_11 "汇流排9单体最小电压";
CM_ SG_ 2336353947 M2P_SysAvgVolt_B9_11 "汇流排9单体平均电压";
CM_ SG_ 2336353947 M2P_BMS_Status_B9 "汇流排9能量状态";
CM_ SG_ 2336353947 M2P_SOC_B9 "汇流排9系统SOC";
CM_ SG_ 2336353947 M2P_SOH_B9 "汇流排9系统SOH";
CM_ SG_ 2336353947 Reserved_11 "预留";
CM_ SG_ 2336353948 M2P_SysMinVolt_B9_12 "汇流排9单体最小电压";
CM_ SG_ 2336353948 M2P_SysAvgVolt_B9_12 "汇流排9单体平均电压";
CM_ SG_ 2336353948 M2P_BMS_Status_B9 "汇流排9能量状态";
CM_ SG_ 2336353948 M2P_SOC_B9 "汇流排9系统SOC";
CM_ SG_ 2336353948 M2P_SOH_B9 "汇流排9系统SOH";
CM_ SG_ 2336353948 Reserved_12 "预留";
CM_ SG_ 2336353949 M2P_SysMinVolt_B9_13 "汇流排9单体最小电压";
CM_ SG_ 2336353949 M2P_SysAvgVolt_B9_13 "汇流排9单体平均电压";
CM_ SG_ 2336353949 M2P_BMS_Status_B9 "汇流排9能量状态";
CM_ SG_ 2336353949 M2P_SOC_B9 "汇流排9系统SOC";
CM_ SG_ 2336353949 M2P_SOH_B9 "汇流排9系统SOH";
CM_ SG_ 2336353949 Reserved_13 "预留";
CM_ SG_ 2336353950 M2P_SysMinVolt_B9_14 "汇流排9单体最小电压";
CM_ SG_ 2336353950 M2P_SysAvgVolt_B9_14 "汇流排9单体平均电压";
CM_ SG_ 2336353950 M2P_BMS_Status_B9 "汇流排9能量状态";
CM_ SG_ 2336353950 M2P_SOC_B9 "汇流排9系统SOC";
CM_ SG_ 2336353950 M2P_SOH_B9 "汇流排9系统SOH";
CM_ SG_ 2336353950 Reserved_14 "预留";
CM_ SG_ 2336353951 M2P_SysMinVolt_B9_15 "汇流排9单体最小电压";
CM_ SG_ 2336353951 M2P_SysAvgVolt_B9_15 "汇流排9单体平均电压";
CM_ SG_ 2336353951 M2P_BMS_Status_B9 "汇流排9能量状态";
CM_ SG_ 2336353951 M2P_SOC_B9 "汇流排9系统SOC";
CM_ SG_ 2336353951 M2P_SOH_B9 "汇流排9系统SOH";
CM_ SG_ 2336353951 Reserved_15 "预留";
CM_ SG_ 2336353952 M2P_SysMinVolt_B9_16 "汇流排9单体最小电压";
CM_ SG_ 2336353952 M2P_SysAvgVolt_B9_16 "汇流排9单体平均电压";
CM_ SG_ 2336353952 M2P_BMS_Status_B9 "汇流排9能量状态";
CM_ SG_ 2336353952 M2P_SOC_B9 "汇流排9系统SOC";
CM_ SG_ 2336353952 M2P_SOH_B9 "汇流排9系统SOH";
CM_ SG_ 2336353952 Reserved_16 "预留";
CM_ SG_ 2336353953 M2P_SysMinVolt_B9_17 "汇流排9单体最小电压";
CM_ SG_ 2336353953 M2P_SysAvgVolt_B9_17 "汇流排9单体平均电压";
CM_ SG_ 2336353953 M2P_BMS_Status_B9 "汇流排9能量状态";
CM_ SG_ 2336353953 M2P_SOC_B9 "汇流排9系统SOC";
CM_ SG_ 2336353953 M2P_SOH_B9 "汇流排9系统SOH";
CM_ SG_ 2336353953 Reserved_17 "预留";
CM_ SG_ 2336353954 M2P_SysMinVolt_B9_18 "汇流排9单体最小电压";
CM_ SG_ 2336353954 M2P_SysAvgVolt_B9_18 "汇流排9单体平均电压";
CM_ SG_ 2336353954 M2P_BMS_Status_B9 "汇流排9能量状态";
CM_ SG_ 2336353954 M2P_SOC_B9 "汇流排9系统SOC";
CM_ SG_ 2336353954 M2P_SOH_B9 "汇流排9系统SOH";
CM_ SG_ 2336353954 Reserved_18 "预留";
CM_ SG_ 2336353955 M2P_SysMinVolt_B9_19 "汇流排9单体最小电压";
CM_ SG_ 2336353955 M2P_SysAvgVolt_B9_19 "汇流排9单体平均电压";
CM_ SG_ 2336353955 M2P_BMS_Status_B9 "汇流排9能量状态";
CM_ SG_ 2336353955 M2P_SOC_B9 "汇流排9系统SOC";
CM_ SG_ 2336353955 M2P_SOH_B9 "汇流排9系统SOH";
CM_ SG_ 2336353955 Reserved_19 "预留";
CM_ SG_ 2336353956 M2P_SysMinVolt_B9_20 "汇流排9单体最小电压";
CM_ SG_ 2336353956 M2P_SysAvgVolt_B9_20 "汇流排9单体平均电压";
CM_ SG_ 2336353956 M2P_BMS_Status_B9 "汇流排9能量状态";
CM_ SG_ 2336353956 M2P_SOC_B9 "汇流排9系统SOC";
CM_ SG_ 2336353956 M2P_SOH_B9 "汇流排9系统SOH";
CM_ SG_ 2336353956 Reserved_20 "预留";
CM_ SG_ 2336353957 M2P_SysMinVolt_B9_21 "汇流排9单体最小电压";
CM_ SG_ 2336353957 M2P_SysAvgVolt_B9_21 "汇流排9单体平均电压";
CM_ SG_ 2336353957 M2P_BMS_Status_B9 "汇流排9能量状态";
CM_ SG_ 2336353957 M2P_SOC_B9 "汇流排9系统SOC";
CM_ SG_ 2336353957 M2P_SOH_B9 "汇流排9系统SOH";
CM_ SG_ 2336353957 Reserved_21 "预留";
CM_ SG_ 2336353958 M2P_SysMinVolt_B9_22 "汇流排9单体最小电压";
CM_ SG_ 2336353958 M2P_SysAvgVolt_B9_22 "汇流排9单体平均电压";
CM_ SG_ 2336353958 M2P_BMS_Status_B9 "汇流排9能量状态";
CM_ SG_ 2336353958 M2P_SOC_B9 "汇流排9系统SOC";
CM_ SG_ 2336353958 M2P_SOH_B9 "汇流排9系统SOH";
CM_ SG_ 2336353958 Reserved_22 "预留";
CM_ SG_ 2336353959 M2P_SysMinVolt_B9_23 "汇流排9单体最小电压";
CM_ SG_ 2336353959 M2P_SysAvgVolt_B9_23 "汇流排9单体平均电压";
CM_ SG_ 2336353959 M2P_BMS_Status_B9 "汇流排9能量状态";
CM_ SG_ 2336353959 M2P_SOC_B9 "汇流排9系统SOC";
CM_ SG_ 2336353959 M2P_SOH_B9 "汇流排9系统SOH";
CM_ SG_ 2336353959 Reserved_23 "预留";
CM_ SG_ 2336353960 M2P_SysMinVolt_B9_24 "汇流排9单体最小电压";
CM_ SG_ 2336353960 M2P_SysAvgVolt_B9_24 "汇流排9单体平均电压";
CM_ SG_ 2336353960 M2P_BMS_Status_B9 "汇流排9能量状态";
CM_ SG_ 2336353960 M2P_SOC_B9 "汇流排9系统SOC";
CM_ SG_ 2336353960 M2P_SOH_B9 "汇流排9系统SOH";
CM_ SG_ 2336353960 Reserved_24 "预留";
CM_ SG_ 2336353961 M2P_SysMinVolt_B9_25 "汇流排9单体最小电压";
CM_ SG_ 2336353961 M2P_SysAvgVolt_B9_25 "汇流排9单体平均电压";
CM_ SG_ 2336353961 M2P_BMS_Status_B9 "汇流排9能量状态";
CM_ SG_ 2336353961 M2P_SOC_B9 "汇流排9系统SOC";
CM_ SG_ 2336353961 M2P_SOH_B9 "汇流排9系统SOH";
CM_ SG_ 2336353961 Reserved_25 "预留";
CM_ SG_ 2336353962 M2P_SysMinVolt_B9_26 "汇流排9单体最小电压";
CM_ SG_ 2336353962 M2P_SysAvgVolt_B9_26 "汇流排9单体平均电压";
CM_ SG_ 2336353962 M2P_BMS_Status_B9 "汇流排9能量状态";
CM_ SG_ 2336353962 M2P_SOC_B9 "汇流排9系统SOC";
CM_ SG_ 2336353962 M2P_SOH_B9 "汇流排9系统SOH";
CM_ SG_ 2336353962 Reserved_26 "预留";
CM_ SG_ 2336353963 M2P_SysMinVolt_B9_27 "汇流排9单体最小电压";
CM_ SG_ 2336353963 M2P_SysAvgVolt_B9_27 "汇流排9单体平均电压";
CM_ SG_ 2336353963 M2P_BMS_Status_B9 "汇流排9能量状态";
CM_ SG_ 2336353963 M2P_SOC_B9 "汇流排9系统SOC";
CM_ SG_ 2336353963 M2P_SOH_B9 "汇流排9系统SOH";
CM_ SG_ 2336353963 Reserved_27 "预留";
CM_ SG_ 2336353964 M2P_SysMinVolt_B9_28 "汇流排9单体最小电压";
CM_ SG_ 2336353964 M2P_SysAvgVolt_B9_28 "汇流排9单体平均电压";
CM_ SG_ 2336353964 M2P_BMS_Status_B9 "汇流排9能量状态";
CM_ SG_ 2336353964 M2P_SOC_B9 "汇流排9系统SOC";
CM_ SG_ 2336353964 M2P_SOH_B9 "汇流排9系统SOH";
CM_ SG_ 2336353964 Reserved_28 "预留";
CM_ SG_ 2336353965 M2P_SysMinVolt_B9_29 "汇流排9单体最小电压";
CM_ SG_ 2336353965 M2P_SysAvgVolt_B9_29 "汇流排9单体平均电压";
CM_ SG_ 2336353965 M2P_BMS_Status_B9 "汇流排9能量状态";
CM_ SG_ 2336353965 M2P_SOC_B9 "汇流排9系统SOC";
CM_ SG_ 2336353965 M2P_SOH_B9 "汇流排9系统SOH";
CM_ SG_ 2336353965 Reserved_29 "预留";
CM_ SG_ 2336353966 M2P_SysMinVolt_B9_30 "汇流排9单体最小电压";
CM_ SG_ 2336353966 M2P_SysAvgVolt_B9_30 "汇流排9单体平均电压";
CM_ SG_ 2336353966 M2P_BMS_Status_B9 "汇流排9能量状态";
CM_ SG_ 2336353966 M2P_SOC_B9 "汇流排9系统SOC";
CM_ SG_ 2336353966 M2P_SOH_B9 "汇流排9系统SOH";
CM_ SG_ 2336353966 Reserved_30 "预留";
CM_ SG_ 2336353967 M2P_SysMinVolt_B9_31 "汇流排9单体最小电压";
CM_ SG_ 2336353967 M2P_SysAvgVolt_B9_31 "汇流排9单体平均电压";
CM_ SG_ 2336353967 M2P_BMS_Status_B9 "汇流排9能量状态";
CM_ SG_ 2336353967 M2P_SOC_B9 "汇流排9系统SOC";
CM_ SG_ 2336353967 M2P_SOH_B9 "汇流排9系统SOH";
CM_ SG_ 2336353967 Reserved_31 "预留";
CM_ SG_ 2336419473 M2P_SOE_Charge_B9 "汇流排9系可充电SOE";
CM_ SG_ 2336419473 M2P_SOE_Discharge_B9 "汇流排9系可放电SOE";
CM_ SG_ 2336419473 Reserved_01 "预留";
CM_ SG_ 2336419474 M2P_SOE_Charge_B9 "汇流排9系可充电SOE";
CM_ SG_ 2336419474 M2P_SOE_Discharge_B9 "汇流排9系可放电SOE";
CM_ SG_ 2336419474 Reserved_02 "预留";
CM_ SG_ 2336419475 M2P_SOE_Charge_B9 "汇流排9系可充电SOE";
CM_ SG_ 2336419475 M2P_SOE_Discharge_B9 "汇流排9系可放电SOE";
CM_ SG_ 2336419475 Reserved_03 "预留";
CM_ SG_ 2336419476 M2P_SOE_Charge_B9 "汇流排9系可充电SOE";
CM_ SG_ 2336419476 M2P_SOE_Discharge_B9 "汇流排9系可放电SOE";
CM_ SG_ 2336419476 Reserved_04 "预留";
CM_ SG_ 2336419477 M2P_SOE_Charge_B9 "汇流排9系可充电SOE";
CM_ SG_ 2336419477 M2P_SOE_Discharge_B9 "汇流排9系可放电SOE";
CM_ SG_ 2336419477 Reserved_05 "预留";
CM_ SG_ 2336419478 M2P_SOE_Charge_B9 "汇流排9系可充电SOE";
CM_ SG_ 2336419478 M2P_SOE_Discharge_B9 "汇流排9系可放电SOE";
CM_ SG_ 2336419478 Reserved_06 "预留";
CM_ SG_ 2336419479 M2P_SOE_Charge_B9 "汇流排9系可充电SOE";
CM_ SG_ 2336419479 M2P_SOE_Discharge_B9 "汇流排9系可放电SOE";
CM_ SG_ 2336419479 Reserved_07 "预留";
CM_ SG_ 2336419480 M2P_SOE_Charge_B9 "汇流排9系可充电SOE";
CM_ SG_ 2336419480 M2P_SOE_Discharge_B9 "汇流排9系可放电SOE";
CM_ SG_ 2336419480 Reserved_08 "预留";
CM_ SG_ 2336419481 M2P_SOE_Charge_B9 "汇流排9系可充电SOE";
CM_ SG_ 2336419481 M2P_SOE_Discharge_B9 "汇流排9系可放电SOE";
CM_ SG_ 2336419481 Reserved_09 "预留";
CM_ SG_ 2336419482 M2P_SOE_Charge_B9 "汇流排9系可充电SOE";
CM_ SG_ 2336419482 M2P_SOE_Discharge_B9 "汇流排9系可放电SOE";
CM_ SG_ 2336419482 Reserved_10 "预留";
CM_ SG_ 2336419483 M2P_SOE_Charge_B9 "汇流排9系可充电SOE";
CM_ SG_ 2336419483 M2P_SOE_Discharge_B9 "汇流排9系可放电SOE";
CM_ SG_ 2336419483 Reserved_11 "预留";
CM_ SG_ 2336419484 M2P_SOE_Charge_B9 "汇流排9系可充电SOE";
CM_ SG_ 2336419484 M2P_SOE_Discharge_B9 "汇流排9系可放电SOE";
CM_ SG_ 2336419484 Reserved_12 "预留";
CM_ SG_ 2336419485 M2P_SOE_Charge_B9 "汇流排9系可充电SOE";
CM_ SG_ 2336419485 M2P_SOE_Discharge_B9 "汇流排9系可放电SOE";
CM_ SG_ 2336419485 Reserved_13 "预留";
CM_ SG_ 2336419486 M2P_SOE_Charge_B9 "汇流排9系可充电SOE";
CM_ SG_ 2336419486 M2P_SOE_Discharge_B9 "汇流排9系可放电SOE";
CM_ SG_ 2336419486 Reserved_14 "预留";
CM_ SG_ 2336419487 M2P_SOE_Charge_B9 "汇流排9系可充电SOE";
CM_ SG_ 2336419487 M2P_SOE_Discharge_B9 "汇流排9系可放电SOE";
CM_ SG_ 2336419487 Reserved_15 "预留";
CM_ SG_ 2336419488 M2P_SOE_Charge_B9 "汇流排9系可充电SOE";
CM_ SG_ 2336419488 M2P_SOE_Discharge_B9 "汇流排9系可放电SOE";
CM_ SG_ 2336419488 Reserved_16 "预留";
CM_ SG_ 2336419489 M2P_SOE_Charge_B9 "汇流排9系可充电SOE";
CM_ SG_ 2336419489 M2P_SOE_Discharge_B9 "汇流排9系可放电SOE";
CM_ SG_ 2336419489 Reserved_17 "预留";
CM_ SG_ 2336419490 M2P_SOE_Charge_B9 "汇流排9系可充电SOE";
CM_ SG_ 2336419490 M2P_SOE_Discharge_B9 "汇流排9系可放电SOE";
CM_ SG_ 2336419490 Reserved_18 "预留";
CM_ SG_ 2336419491 M2P_SOE_Charge_B9 "汇流排9系可充电SOE";
CM_ SG_ 2336419491 M2P_SOE_Discharge_B9 "汇流排9系可放电SOE";
CM_ SG_ 2336419491 Reserved_19 "预留";
CM_ SG_ 2336419492 M2P_SOE_Charge_B9 "汇流排9系可充电SOE";
CM_ SG_ 2336419492 M2P_SOE_Discharge_B9 "汇流排9系可放电SOE";
CM_ SG_ 2336419492 Reserved_20 "预留";
CM_ SG_ 2336419493 M2P_SOE_Charge_B9 "汇流排9系可充电SOE";
CM_ SG_ 2336419493 M2P_SOE_Discharge_B9 "汇流排9系可放电SOE";
CM_ SG_ 2336419493 Reserved_21 "预留";
CM_ SG_ 2336419494 M2P_SOE_Charge_B9 "汇流排9系可充电SOE";
CM_ SG_ 2336419494 M2P_SOE_Discharge_B9 "汇流排9系可放电SOE";
CM_ SG_ 2336419494 Reserved_22 "预留";
CM_ SG_ 2336419495 M2P_SOE_Charge_B9 "汇流排9系可充电SOE";
CM_ SG_ 2336419495 M2P_SOE_Discharge_B9 "汇流排9系可放电SOE";
CM_ SG_ 2336419495 Reserved_23 "预留";
CM_ SG_ 2336419496 M2P_SOE_Charge_B9 "汇流排9系可充电SOE";
CM_ SG_ 2336419496 M2P_SOE_Discharge_B9 "汇流排9系可放电SOE";
CM_ SG_ 2336419496 Reserved_24 "预留";
CM_ SG_ 2336419497 M2P_SOE_Charge_B9 "汇流排9系可充电SOE";
CM_ SG_ 2336419497 M2P_SOE_Discharge_B9 "汇流排9系可放电SOE";
CM_ SG_ 2336419497 Reserved_25 "预留";
CM_ SG_ 2336419498 M2P_SOE_Charge_B9 "汇流排9系可充电SOE";
CM_ SG_ 2336419498 M2P_SOE_Discharge_B9 "汇流排9系可放电SOE";
CM_ SG_ 2336419498 Reserved_26 "预留";
CM_ SG_ 2336419499 M2P_SOE_Charge_B9 "汇流排9系可充电SOE";
CM_ SG_ 2336419499 M2P_SOE_Discharge_B9 "汇流排9系可放电SOE";
CM_ SG_ 2336419499 Reserved_27 "预留";
CM_ SG_ 2336419500 M2P_SOE_Charge_B9 "汇流排9系可充电SOE";
CM_ SG_ 2336419500 M2P_SOE_Discharge_B9 "汇流排9系可放电SOE";
CM_ SG_ 2336419500 Reserved_28 "预留";
CM_ SG_ 2336419501 M2P_SOE_Charge_B9 "汇流排9系可充电SOE";
CM_ SG_ 2336419501 M2P_SOE_Discharge_B9 "汇流排9系可放电SOE";
CM_ SG_ 2336419501 Reserved_29 "预留";
CM_ SG_ 2336419502 M2P_SOE_Charge_B9 "汇流排9系可充电SOE";
CM_ SG_ 2336419502 M2P_SOE_Discharge_B9 "汇流排9系可放电SOE";
CM_ SG_ 2336419502 Reserved_30 "预留";
CM_ SG_ 2336419503 M2P_SOE_Charge_B9 "汇流排9系可充电SOE";
CM_ SG_ 2336419503 M2P_SOE_Discharge_B9 "汇流排9系可放电SOE";
CM_ SG_ 2336419503 Reserved_31 "预留";
CM_ SG_ 2336485009 M2P_Measure_Vol_B10_01 "汇流排10所有高压在线电柜外侧电压平均值    ";
CM_ SG_ 2336485009 M2P_Current_B10_01 "汇流排10所有电柜电流累加和";
CM_ SG_ 2336485009 M2P_PermitMaxCharge_I_B10_01 "汇流排10最大允许充电电流";
CM_ SG_ 2336485009 M2P_PermitMaxDisCharge_I_B10_01 "汇流排10最大允许放电电流";
CM_ SG_ 2336485010 M2P_Measure_Vol_B10_02 "汇流排10所有高压在线电柜外侧电压平均值    ";
CM_ SG_ 2336485010 M2P_Current_B10_02 "汇流排10所有电柜电流累加和";
CM_ SG_ 2336485010 M2P_PermitMaxCharge_I_B10_02 "汇流排10最大允许充电电流";
CM_ SG_ 2336485010 M2P_PermitMaxDisCharge_I_B10_02 "汇流排10最大允许放电电流";
CM_ SG_ 2336485011 M2P_Measure_Vol_B10_03 "汇流排10所有高压在线电柜外侧电压平均值    ";
CM_ SG_ 2336485011 M2P_Current_B10_03 "汇流排10所有电柜电流累加和";
CM_ SG_ 2336485011 M2P_PermitMaxCharge_I_B10_03 "汇流排10最大允许充电电流";
CM_ SG_ 2336485011 M2P_PermitMaxDisCharge_I_B10_03 "汇流排10最大允许放电电流";
CM_ SG_ 2336485012 M2P_Measure_Vol_B10_04 "汇流排10所有高压在线电柜外侧电压平均值    ";
CM_ SG_ 2336485012 M2P_Current_B10_04 "汇流排10所有电柜电流累加和";
CM_ SG_ 2336485012 M2P_PermitMaxCharge_I_B10_04 "汇流排10最大允许充电电流";
CM_ SG_ 2336485012 M2P_PermitMaxDisCharge_I_B10_04 "汇流排10最大允许放电电流";
CM_ SG_ 2336485013 M2P_Measure_Vol_B10_05 "汇流排10所有高压在线电柜外侧电压平均值    ";
CM_ SG_ 2336485013 M2P_Current_B10_05 "汇流排10所有电柜电流累加和";
CM_ SG_ 2336485013 M2P_PermitMaxCharge_I_B10_05 "汇流排10最大允许充电电流";
CM_ SG_ 2336485013 M2P_PermitMaxDisCharge_I_B10_05 "汇流排10最大允许放电电流";
CM_ SG_ 2336485014 M2P_Measure_Vol_B10_06 "汇流排10所有高压在线电柜外侧电压平均值    ";
CM_ SG_ 2336485014 M2P_Current_B10_06 "汇流排10所有电柜电流累加和";
CM_ SG_ 2336485014 M2P_PermitMaxCharge_I_B10_06 "汇流排10最大允许充电电流";
CM_ SG_ 2336485014 M2P_PermitMaxDisCharge_I_B10_06 "汇流排10最大允许放电电流";
CM_ SG_ 2336485015 M2P_Measure_Vol_B10_07 "汇流排10所有高压在线电柜外侧电压平均值    ";
CM_ SG_ 2336485015 M2P_Current_B10_07 "汇流排10所有电柜电流累加和";
CM_ SG_ 2336485015 M2P_PermitMaxCharge_I_B10_07 "汇流排10最大允许充电电流";
CM_ SG_ 2336485015 M2P_PermitMaxDisCharge_I_B10_07 "汇流排10最大允许放电电流";
CM_ SG_ 2336485016 M2P_Measure_Vol_B10_08 "汇流排10所有高压在线电柜外侧电压平均值    ";
CM_ SG_ 2336485016 M2P_Current_B10_08 "汇流排10所有电柜电流累加和";
CM_ SG_ 2336485016 M2P_PermitMaxCharge_I_B10_08 "汇流排10最大允许充电电流";
CM_ SG_ 2336485016 M2P_PermitMaxDisCharge_I_B10_08 "汇流排10最大允许放电电流";
CM_ SG_ 2336485017 M2P_Measure_Vol_B10_09 "汇流排10所有高压在线电柜外侧电压平均值    ";
CM_ SG_ 2336485017 M2P_Current_B10_09 "汇流排10所有电柜电流累加和";
CM_ SG_ 2336485017 M2P_PermitMaxCharge_I_B10_09 "汇流排10最大允许充电电流";
CM_ SG_ 2336485017 M2P_PermitMaxDisCharge_I_B10_09 "汇流排10最大允许放电电流";
CM_ SG_ 2336485018 M2P_Measure_Vol_B10_10 "汇流排10所有高压在线电柜外侧电压平均值    ";
CM_ SG_ 2336485018 M2P_Current_B10_10 "汇流排10所有电柜电流累加和";
CM_ SG_ 2336485018 M2P_PermitMaxCharge_I_B10_10 "汇流排10最大允许充电电流";
CM_ SG_ 2336485018 M2P_PermitMaxDisCharge_I_B10_10 "汇流排10最大允许放电电流";
CM_ SG_ 2336485019 M2P_Measure_Vol_B10_11 "汇流排10所有高压在线电柜外侧电压平均值    ";
CM_ SG_ 2336485019 M2P_Current_B10_11 "汇流排10所有电柜电流累加和";
CM_ SG_ 2336485019 M2P_PermitMaxCharge_I_B10_11 "汇流排10最大允许充电电流";
CM_ SG_ 2336485019 M2P_PermitMaxDisCharge_I_B10_11 "汇流排10最大允许放电电流";
CM_ SG_ 2336485020 M2P_Measure_Vol_B10_12 "汇流排10所有高压在线电柜外侧电压平均值    ";
CM_ SG_ 2336485020 M2P_Current_B10_12 "汇流排10所有电柜电流累加和";
CM_ SG_ 2336485020 M2P_PermitMaxCharge_I_B10_12 "汇流排10最大允许充电电流";
CM_ SG_ 2336485020 M2P_PermitMaxDisCharge_I_B10_12 "汇流排10最大允许放电电流";
CM_ SG_ 2336485021 M2P_Measure_Vol_B10_13 "汇流排10所有高压在线电柜外侧电压平均值    ";
CM_ SG_ 2336485021 M2P_Current_B10_13 "汇流排10所有电柜电流累加和";
CM_ SG_ 2336485021 M2P_PermitMaxCharge_I_B10_13 "汇流排10最大允许充电电流";
CM_ SG_ 2336485021 M2P_PermitMaxDisCharge_I_B10_13 "汇流排10最大允许放电电流";
CM_ SG_ 2336485022 M2P_Measure_Vol_B10_14 "汇流排10所有高压在线电柜外侧电压平均值    ";
CM_ SG_ 2336485022 M2P_Current_B10_14 "汇流排10所有电柜电流累加和";
CM_ SG_ 2336485022 M2P_PermitMaxCharge_I_B10_14 "汇流排10最大允许充电电流";
CM_ SG_ 2336485022 M2P_PermitMaxDisCharge_I_B10_14 "汇流排10最大允许放电电流";
CM_ SG_ 2336485023 M2P_Measure_Vol_B10_15 "汇流排10所有高压在线电柜外侧电压平均值    ";
CM_ SG_ 2336485023 M2P_Current_B10_15 "汇流排10所有电柜电流累加和";
CM_ SG_ 2336485023 M2P_PermitMaxCharge_I_B10_15 "汇流排10最大允许充电电流";
CM_ SG_ 2336485023 M2P_PermitMaxDisCharge_I_B10_15 "汇流排10最大允许放电电流";
VAL_ 2335960721 M2P_SysremEngy_Chg_B8_01 65535 "Invalid" ;
VAL_ 2335960721 M2P_SysremEngy_DisChg_B8_01 65535 "Invalid" ;
VAL_ 2335960722 M2P_SysremEngy_Chg_B8_02 65535 "Invalid" ;
VAL_ 2335960722 M2P_SysremEngy_DisChg_B8_02 65535 "Invalid" ;
VAL_ 2335960723 M2P_SysremEngy_Chg_B8_03 65535 "Invalid" ;
VAL_ 2335960723 M2P_SysremEngy_DisChg_B8_03 65535 "Invalid" ;
VAL_ 2335960724 M2P_SysremEngy_Chg_B8_04 65535 "Invalid" ;
VAL_ 2335960724 M2P_SysremEngy_DisChg_B8_04 65535 "Invalid" ;
VAL_ 2335960725 M2P_SysremEngy_Chg_B8_05 65535 "Invalid" ;
VAL_ 2335960725 M2P_SysremEngy_DisChg_B8_05 65535 "Invalid" ;
VAL_ 2335960726 M2P_SysremEngy_Chg_B8_06 65535 "Invalid" ;
VAL_ 2335960726 M2P_SysremEngy_DisChg_B8_06 65535 "Invalid" ;
VAL_ 2335960727 M2P_SysremEngy_Chg_B8_07 65535 "Invalid" ;
VAL_ 2335960727 M2P_SysremEngy_DisChg_B8_07 65535 "Invalid" ;
VAL_ 2335960728 M2P_SysremEngy_Chg_B8_08 65535 "Invalid" ;
VAL_ 2335960728 M2P_SysremEngy_DisChg_B8_08 65535 "Invalid" ;
VAL_ 2335960729 M2P_SysremEngy_Chg_B8_09 65535 "Invalid" ;
VAL_ 2335960729 M2P_SysremEngy_DisChg_B8_09 65535 "Invalid" ;
VAL_ 2335960730 M2P_SysremEngy_Chg_B8_10 65535 "Invalid" ;
VAL_ 2335960730 M2P_SysremEngy_DisChg_B8_10 65535 "Invalid" ;
VAL_ 2335960731 M2P_SysremEngy_Chg_B8_11 65535 "Invalid" ;
VAL_ 2335960731 M2P_SysremEngy_DisChg_B8_11 65535 "Invalid" ;
VAL_ 2335960732 M2P_SysremEngy_Chg_B8_12 65535 "Invalid" ;
VAL_ 2335960732 M2P_SysremEngy_DisChg_B8_12 65535 "Invalid" ;
VAL_ 2335960733 M2P_SysremEngy_Chg_B8_13 65535 "Invalid" ;
VAL_ 2335960733 M2P_SysremEngy_DisChg_B8_13 65535 "Invalid" ;
VAL_ 2335960734 M2P_SysremEngy_Chg_B8_14 65535 "Invalid" ;
VAL_ 2335960734 M2P_SysremEngy_DisChg_B8_14 65535 "Invalid" ;
VAL_ 2335960735 M2P_SysremEngy_Chg_B8_15 65535 "Invalid" ;
VAL_ 2335960735 M2P_SysremEngy_DisChg_B8_15 65535 "Invalid" ;
VAL_ 2335960736 M2P_SysremEngy_Chg_B8_16 65535 "Invalid" ;
VAL_ 2335960736 M2P_SysremEngy_DisChg_B8_16 65535 "Invalid" ;
VAL_ 2335960737 M2P_SysremEngy_Chg_B8_17 65535 "Invalid" ;
VAL_ 2335960737 M2P_SysremEngy_DisChg_B8_17 65535 "Invalid" ;
VAL_ 2335960738 M2P_SysremEngy_Chg_B8_18 65535 "Invalid" ;
VAL_ 2335960738 M2P_SysremEngy_DisChg_B8_18 65535 "Invalid" ;
VAL_ 2335960739 M2P_SysremEngy_Chg_B8_19 65535 "Invalid" ;
VAL_ 2335960739 M2P_SysremEngy_DisChg_B8_19 65535 "Invalid" ;
VAL_ 2335960740 M2P_SysremEngy_Chg_B8_20 65535 "Invalid" ;
VAL_ 2335960740 M2P_SysremEngy_DisChg_B8_20 65535 "Invalid" ;
VAL_ 2335960741 M2P_SysremEngy_Chg_B8_21 65535 "Invalid" ;
VAL_ 2335960741 M2P_SysremEngy_DisChg_B8_21 65535 "Invalid" ;
VAL_ 2335960742 M2P_SysremEngy_Chg_B8_22 65535 "Invalid" ;
VAL_ 2335960742 M2P_SysremEngy_DisChg_B8_22 65535 "Invalid" ;
VAL_ 2335960743 M2P_SysremEngy_Chg_B8_23 65535 "Invalid" ;
VAL_ 2335960743 M2P_SysremEngy_DisChg_B8_23 65535 "Invalid" ;
VAL_ 2335960744 M2P_SysremEngy_Chg_B8_24 65535 "Invalid" ;
VAL_ 2335960744 M2P_SysremEngy_DisChg_B8_24 65535 "Invalid" ;
VAL_ 2335960745 M2P_SysremEngy_Chg_B8_25 65535 "Invalid" ;
VAL_ 2335960745 M2P_SysremEngy_DisChg_B8_25 65535 "Invalid" ;
VAL_ 2335960746 M2P_SysremEngy_Chg_B8_26 65535 "Invalid" ;
VAL_ 2335960746 M2P_SysremEngy_DisChg_B8_26 65535 "Invalid" ;
VAL_ 2335960747 M2P_SysremEngy_Chg_B8_27 65535 "Invalid" ;
VAL_ 2335960747 M2P_SysremEngy_DisChg_B8_27 65535 "Invalid" ;
VAL_ 2335960748 M2P_SysremEngy_Chg_B8_28 65535 "Invalid" ;
VAL_ 2335960748 M2P_SysremEngy_DisChg_B8_28 65535 "Invalid" ;
VAL_ 2335960749 M2P_SysremEngy_Chg_B8_29 65535 "Invalid" ;
VAL_ 2335960749 M2P_SysremEngy_DisChg_B8_29 65535 "Invalid" ;
VAL_ 2335960750 M2P_SysremEngy_Chg_B8_30 65535 "Invalid" ;
VAL_ 2335960750 M2P_SysremEngy_DisChg_B8_30 65535 "Invalid" ;
VAL_ 2335960751 M2P_SysremEngy_Chg_B8_31 65535 "Invalid" ;
VAL_ 2335960751 M2P_SysremEngy_DisChg_B8_31 65535 "Invalid" ;
VAL_ 2336026257 M2P_BMS_Status_B8 0 "初始化状态" 1 "非满充满放状态" 2 "满充状态" 3 "满放状态" ;
VAL_ 2336026257 M2P_SOC_B8 1023 "Null" ;
VAL_ 2336026257 M2P_SOH_B8 255 "Null" ;
VAL_ 2336026258 M2P_BMS_Status_B8 0 "初始化状态" 1 "非满充满放状态" 2 "满充状态" 3 "满放状态" ;
VAL_ 2336026258 M2P_SOC_B8 1023 "Null" ;
VAL_ 2336026258 M2P_SOH_B8 255 "Null" ;
VAL_ 2336026259 M2P_BMS_Status_B8 0 "初始化状态" 1 "非满充满放状态" 2 "满充状态" 3 "满放状态" ;
VAL_ 2336026259 M2P_SOC_B8 1023 "Null" ;
VAL_ 2336026259 M2P_SOH_B8 255 "Null" ;
VAL_ 2336026260 M2P_BMS_Status_B8 0 "初始化状态" 1 "非满充满放状态" 2 "满充状态" 3 "满放状态" ;
VAL_ 2336026260 M2P_SOC_B8 1023 "Null" ;
VAL_ 2336026260 M2P_SOH_B8 255 "Null" ;
VAL_ 2336026261 M2P_BMS_Status_B8 0 "初始化状态" 1 "非满充满放状态" 2 "满充状态" 3 "满放状态" ;
VAL_ 2336026261 M2P_SOC_B8 1023 "Null" ;
VAL_ 2336026261 M2P_SOH_B8 255 "Null" ;
VAL_ 2336026262 M2P_BMS_Status_B8 0 "初始化状态" 1 "非满充满放状态" 2 "满充状态" 3 "满放状态" ;
VAL_ 2336026262 M2P_SOC_B8 1023 "Null" ;
VAL_ 2336026262 M2P_SOH_B8 255 "Null" ;
VAL_ 2336026263 M2P_BMS_Status_B8 0 "初始化状态" 1 "非满充满放状态" 2 "满充状态" 3 "满放状态" ;
VAL_ 2336026263 M2P_SOC_B8 1023 "Null" ;
VAL_ 2336026263 M2P_SOH_B8 255 "Null" ;
VAL_ 2336026264 M2P_BMS_Status_B8 0 "初始化状态" 1 "非满充满放状态" 2 "满充状态" 3 "满放状态" ;
VAL_ 2336026264 M2P_SOC_B8 1023 "Null" ;
VAL_ 2336026264 M2P_SOH_B8 255 "Null" ;
VAL_ 2336026265 M2P_BMS_Status_B8 0 "初始化状态" 1 "非满充满放状态" 2 "满充状态" 3 "满放状态" ;
VAL_ 2336026265 M2P_SOC_B8 1023 "Null" ;
VAL_ 2336026265 M2P_SOH_B8 255 "Null" ;
VAL_ 2336026266 M2P_BMS_Status_B8 0 "初始化状态" 1 "非满充满放状态" 2 "满充状态" 3 "满放状态" ;
VAL_ 2336026266 M2P_SOC_B8 1023 "Null" ;
VAL_ 2336026266 M2P_SOH_B8 255 "Null" ;
VAL_ 2336026267 M2P_BMS_Status_B8 0 "初始化状态" 1 "非满充满放状态" 2 "满充状态" 3 "满放状态" ;
VAL_ 2336026267 M2P_SOC_B8 1023 "Null" ;
VAL_ 2336026267 M2P_SOH_B8 255 "Null" ;
VAL_ 2336026268 M2P_BMS_Status_B8 0 "初始化状态" 1 "非满充满放状态" 2 "满充状态" 3 "满放状态" ;
VAL_ 2336026268 M2P_SOC_B8 1023 "Null" ;
VAL_ 2336026268 M2P_SOH_B8 255 "Null" ;
VAL_ 2336026269 M2P_BMS_Status_B8 0 "初始化状态" 1 "非满充满放状态" 2 "满充状态" 3 "满放状态" ;
VAL_ 2336026269 M2P_SOC_B8 1023 "Null" ;
VAL_ 2336026269 M2P_SOH_B8 255 "Null" ;
VAL_ 2336026270 M2P_BMS_Status_B8 0 "初始化状态" 1 "非满充满放状态" 2 "满充状态" 3 "满放状态" ;
VAL_ 2336026270 M2P_SOC_B8 1023 "Null" ;
VAL_ 2336026270 M2P_SOH_B8 255 "Null" ;
VAL_ 2336026271 M2P_BMS_Status_B8 0 "初始化状态" 1 "非满充满放状态" 2 "满充状态" 3 "满放状态" ;
VAL_ 2336026271 M2P_SOC_B8 1023 "Null" ;
VAL_ 2336026271 M2P_SOH_B8 255 "Null" ;
VAL_ 2336026272 M2P_BMS_Status_B8 0 "初始化状态" 1 "非满充满放状态" 2 "满充状态" 3 "满放状态" ;
VAL_ 2336026272 M2P_SOC_B8 1023 "Null" ;
VAL_ 2336026272 M2P_SOH_B8 255 "Null" ;
VAL_ 2336026273 M2P_BMS_Status_B8 0 "初始化状态" 1 "非满充满放状态" 2 "满充状态" 3 "满放状态" ;
VAL_ 2336026273 M2P_SOC_B8 1023 "Null" ;
VAL_ 2336026273 M2P_SOH_B8 255 "Null" ;
VAL_ 2336026274 M2P_BMS_Status_B8 0 "初始化状态" 1 "非满充满放状态" 2 "满充状态" 3 "满放状态" ;
VAL_ 2336026274 M2P_SOC_B8 1023 "Null" ;
VAL_ 2336026274 M2P_SOH_B8 255 "Null" ;
VAL_ 2336026275 M2P_BMS_Status_B8 0 "初始化状态" 1 "非满充满放状态" 2 "满充状态" 3 "满放状态" ;
VAL_ 2336026275 M2P_SOC_B8 1023 "Null" ;
VAL_ 2336026275 M2P_SOH_B8 255 "Null" ;
VAL_ 2336026276 M2P_BMS_Status_B8 0 "初始化状态" 1 "非满充满放状态" 2 "满充状态" 3 "满放状态" ;
VAL_ 2336026276 M2P_SOC_B8 1023 "Null" ;
VAL_ 2336026276 M2P_SOH_B8 255 "Null" ;
VAL_ 2336026277 M2P_BMS_Status_B8 0 "初始化状态" 1 "非满充满放状态" 2 "满充状态" 3 "满放状态" ;
VAL_ 2336026277 M2P_SOC_B8 1023 "Null" ;
VAL_ 2336026277 M2P_SOH_B8 255 "Null" ;
VAL_ 2336026278 M2P_BMS_Status_B8 0 "初始化状态" 1 "非满充满放状态" 2 "满充状态" 3 "满放状态" ;
VAL_ 2336026278 M2P_SOC_B8 1023 "Null" ;
VAL_ 2336026278 M2P_SOH_B8 255 "Null" ;
VAL_ 2336026279 M2P_BMS_Status_B8 0 "初始化状态" 1 "非满充满放状态" 2 "满充状态" 3 "满放状态" ;
VAL_ 2336026279 M2P_SOC_B8 1023 "Null" ;
VAL_ 2336026279 M2P_SOH_B8 255 "Null" ;
VAL_ 2336026280 M2P_BMS_Status_B8 0 "初始化状态" 1 "非满充满放状态" 2 "满充状态" 3 "满放状态" ;
VAL_ 2336026280 M2P_SOC_B8 1023 "Null" ;
VAL_ 2336026280 M2P_SOH_B8 255 "Null" ;
VAL_ 2336026281 M2P_BMS_Status_B8 0 "初始化状态" 1 "非满充满放状态" 2 "满充状态" 3 "满放状态" ;
VAL_ 2336026281 M2P_SOC_B8 1023 "Null" ;
VAL_ 2336026281 M2P_SOH_B8 255 "Null" ;
VAL_ 2336026282 M2P_BMS_Status_B8 0 "初始化状态" 1 "非满充满放状态" 2 "满充状态" 3 "满放状态" ;
VAL_ 2336026282 M2P_SOC_B8 1023 "Null" ;
VAL_ 2336026282 M2P_SOH_B8 255 "Null" ;
VAL_ 2336026283 M2P_BMS_Status_B8 0 "初始化状态" 1 "非满充满放状态" 2 "满充状态" 3 "满放状态" ;
VAL_ 2336026283 M2P_SOC_B8 1023 "Null" ;
VAL_ 2336026283 M2P_SOH_B8 255 "Null" ;
VAL_ 2336026284 M2P_BMS_Status_B8 0 "初始化状态" 1 "非满充满放状态" 2 "满充状态" 3 "满放状态" ;
VAL_ 2336026284 M2P_SOC_B8 1023 "Null" ;
VAL_ 2336026284 M2P_SOH_B8 255 "Null" ;
VAL_ 2336026285 M2P_BMS_Status_B8 0 "初始化状态" 1 "非满充满放状态" 2 "满充状态" 3 "满放状态" ;
VAL_ 2336026285 M2P_SOC_B8 1023 "Null" ;
VAL_ 2336026285 M2P_SOH_B8 255 "Null" ;
VAL_ 2336026286 M2P_BMS_Status_B8 0 "初始化状态" 1 "非满充满放状态" 2 "满充状态" 3 "满放状态" ;
VAL_ 2336026286 M2P_SOC_B8 1023 "Null" ;
VAL_ 2336026286 M2P_SOH_B8 255 "Null" ;
VAL_ 2336026287 M2P_BMS_Status_B8 0 "初始化状态" 1 "非满充满放状态" 2 "满充状态" 3 "满放状态" ;
VAL_ 2336026287 M2P_SOC_B8 1023 "Null" ;
VAL_ 2336026287 M2P_SOH_B8 255 "Null" ;
VAL_ 2336091793 M2P_SOE_Charge_B8 1023 "Null" ;
VAL_ 2336091793 M2P_SOE_Discharge_B8 1023 "Null" ;
VAL_ 2336091794 M2P_SOE_Charge_B8 1023 "Null" ;
VAL_ 2336091794 M2P_SOE_Discharge_B8 1023 "Null" ;
VAL_ 2336091795 M2P_SOE_Charge_B8 1023 "Null" ;
VAL_ 2336091795 M2P_SOE_Discharge_B8 1023 "Null" ;
VAL_ 2336091796 M2P_SOE_Charge_B8 1023 "Null" ;
VAL_ 2336091796 M2P_SOE_Discharge_B8 1023 "Null" ;
VAL_ 2336091797 M2P_SOE_Charge_B8 1023 "Null" ;
VAL_ 2336091797 M2P_SOE_Discharge_B8 1023 "Null" ;
VAL_ 2336091798 M2P_SOE_Charge_B8 1023 "Null" ;
VAL_ 2336091798 M2P_SOE_Discharge_B8 1023 "Null" ;
VAL_ 2336091799 M2P_SOE_Charge_B8 1023 "Null" ;
VAL_ 2336091799 M2P_SOE_Discharge_B8 1023 "Null" ;
VAL_ 2336091800 M2P_SOE_Charge_B8 1023 "Null" ;
VAL_ 2336091800 M2P_SOE_Discharge_B8 1023 "Null" ;
VAL_ 2336091801 M2P_SOE_Charge_B8 1023 "Null" ;
VAL_ 2336091801 M2P_SOE_Discharge_B8 1023 "Null" ;
VAL_ 2336091802 M2P_SOE_Charge_B8 1023 "Null" ;
VAL_ 2336091802 M2P_SOE_Discharge_B8 1023 "Null" ;
VAL_ 2336091803 M2P_SOE_Charge_B8 1023 "Null" ;
VAL_ 2336091803 M2P_SOE_Discharge_B8 1023 "Null" ;
VAL_ 2336091804 M2P_SOE_Charge_B8 1023 "Null" ;
VAL_ 2336091804 M2P_SOE_Discharge_B8 1023 "Null" ;
VAL_ 2336091805 M2P_SOE_Charge_B8 1023 "Null" ;
VAL_ 2336091805 M2P_SOE_Discharge_B8 1023 "Null" ;
VAL_ 2336091806 M2P_SOE_Charge_B8 1023 "Null" ;
VAL_ 2336091806 M2P_SOE_Discharge_B8 1023 "Null" ;
VAL_ 2336091807 M2P_SOE_Charge_B8 1023 "Null" ;
VAL_ 2336091807 M2P_SOE_Discharge_B8 1023 "Null" ;
VAL_ 2336091808 M2P_SOE_Charge_B8 1023 "Null" ;
VAL_ 2336091808 M2P_SOE_Discharge_B8 1023 "Null" ;
VAL_ 2336091809 M2P_SOE_Charge_B8 1023 "Null" ;
VAL_ 2336091809 M2P_SOE_Discharge_B8 1023 "Null" ;
VAL_ 2336091810 M2P_SOE_Charge_B8 1023 "Null" ;
VAL_ 2336091810 M2P_SOE_Discharge_B8 1023 "Null" ;
VAL_ 2336091811 M2P_SOE_Charge_B8 1023 "Null" ;
VAL_ 2336091811 M2P_SOE_Discharge_B8 1023 "Null" ;
VAL_ 2336091812 M2P_SOE_Charge_B8 1023 "Null" ;
VAL_ 2336091812 M2P_SOE_Discharge_B8 1023 "Null" ;
VAL_ 2336091813 M2P_SOE_Charge_B8 1023 "Null" ;
VAL_ 2336091813 M2P_SOE_Discharge_B8 1023 "Null" ;
VAL_ 2336091814 M2P_SOE_Charge_B8 1023 "Null" ;
VAL_ 2336091814 M2P_SOE_Discharge_B8 1023 "Null" ;
VAL_ 2336091815 M2P_SOE_Charge_B8 1023 "Null" ;
VAL_ 2336091815 M2P_SOE_Discharge_B8 1023 "Null" ;
VAL_ 2336091816 M2P_SOE_Charge_B8 1023 "Null" ;
VAL_ 2336091816 M2P_SOE_Discharge_B8 1023 "Null" ;
VAL_ 2336091817 M2P_SOE_Charge_B8 1023 "Null" ;
VAL_ 2336091817 M2P_SOE_Discharge_B8 1023 "Null" ;
VAL_ 2336091818 M2P_SOE_Charge_B8 1023 "Null" ;
VAL_ 2336091818 M2P_SOE_Discharge_B8 1023 "Null" ;
VAL_ 2336091819 M2P_SOE_Charge_B8 1023 "Null" ;
VAL_ 2336091819 M2P_SOE_Discharge_B8 1023 "Null" ;
VAL_ 2336091820 M2P_SOE_Charge_B8 1023 "Null" ;
VAL_ 2336091820 M2P_SOE_Discharge_B8 1023 "Null" ;
VAL_ 2336091821 M2P_SOE_Charge_B8 1023 "Null" ;
VAL_ 2336091821 M2P_SOE_Discharge_B8 1023 "Null" ;
VAL_ 2336091822 M2P_SOE_Charge_B8 1023 "Null" ;
VAL_ 2336091822 M2P_SOE_Discharge_B8 1023 "Null" ;
VAL_ 2336091823 M2P_SOE_Charge_B8 1023 "Null" ;
VAL_ 2336091823 M2P_SOE_Discharge_B8 1023 "Null" ;
VAL_ 2336157329 M2P_Measure_Vol_B9_01 65535 "Invalid" ;
VAL_ 2336157329 M2P_Current_B9_01 65535 "Invalid" ;
VAL_ 2336157329 M2P_PermitMaxCharge_I_B9_01 65535 "Invalid" ;
VAL_ 2336157329 M2P_PermitMaxDisCharge_I_B9_01 65535 "Invalid" ;
VAL_ 2336157330 M2P_Measure_Vol_B9_02 65535 "Invalid" ;
VAL_ 2336157330 M2P_Current_B9_02 65535 "Invalid" ;
VAL_ 2336157330 M2P_PermitMaxCharge_I_B9_02 65535 "Invalid" ;
VAL_ 2336157330 M2P_PermitMaxDisCharge_I_B9_02 65535 "Invalid" ;
VAL_ 2336157331 M2P_Measure_Vol_B9_03 65535 "Invalid" ;
VAL_ 2336157331 M2P_Current_B9_03 65535 "Invalid" ;
VAL_ 2336157331 M2P_PermitMaxCharge_I_B9_03 65535 "Invalid" ;
VAL_ 2336157331 M2P_PermitMaxDisCharge_I_B9_03 65535 "Invalid" ;
VAL_ 2336157332 M2P_Measure_Vol_B9_04 65535 "Invalid" ;
VAL_ 2336157332 M2P_Current_B9_04 65535 "Invalid" ;
VAL_ 2336157332 M2P_PermitMaxCharge_I_B9_04 65535 "Invalid" ;
VAL_ 2336157332 M2P_PermitMaxDisCharge_I_B9_04 65535 "Invalid" ;
VAL_ 2336157333 M2P_Measure_Vol_B9_05 65535 "Invalid" ;
VAL_ 2336157333 M2P_Current_B9_05 65535 "Invalid" ;
VAL_ 2336157333 M2P_PermitMaxCharge_I_B9_05 65535 "Invalid" ;
VAL_ 2336157333 M2P_PermitMaxDisCharge_I_B9_05 65535 "Invalid" ;
VAL_ 2336157334 M2P_Measure_Vol_B9_06 65535 "Invalid" ;
VAL_ 2336157334 M2P_Current_B9_06 65535 "Invalid" ;
VAL_ 2336157334 M2P_PermitMaxCharge_I_B9_06 65535 "Invalid" ;
VAL_ 2336157334 M2P_PermitMaxDisCharge_I_B9_06 65535 "Invalid" ;
VAL_ 2336157335 M2P_Measure_Vol_B9_07 65535 "Invalid" ;
VAL_ 2336157335 M2P_Current_B9_07 65535 "Invalid" ;
VAL_ 2336157335 M2P_PermitMaxCharge_I_B9_07 65535 "Invalid" ;
VAL_ 2336157335 M2P_PermitMaxDisCharge_I_B9_07 65535 "Invalid" ;
VAL_ 2336157336 M2P_Measure_Vol_B9_08 65535 "Invalid" ;
VAL_ 2336157336 M2P_Current_B9_08 65535 "Invalid" ;
VAL_ 2336157336 M2P_PermitMaxCharge_I_B9_08 65535 "Invalid" ;
VAL_ 2336157336 M2P_PermitMaxDisCharge_I_B9_08 65535 "Invalid" ;
VAL_ 2336157337 M2P_Measure_Vol_B9_09 65535 "Invalid" ;
VAL_ 2336157337 M2P_Current_B9_09 65535 "Invalid" ;
VAL_ 2336157337 M2P_PermitMaxCharge_I_B9_09 65535 "Invalid" ;
VAL_ 2336157337 M2P_PermitMaxDisCharge_I_B9_09 65535 "Invalid" ;
VAL_ 2336157338 M2P_Measure_Vol_B9_10 65535 "Invalid" ;
VAL_ 2336157338 M2P_Current_B9_10 65535 "Invalid" ;
VAL_ 2336157338 M2P_PermitMaxCharge_I_B9_10 65535 "Invalid" ;
VAL_ 2336157338 M2P_PermitMaxDisCharge_I_B9_10 65535 "Invalid" ;
VAL_ 2336157339 M2P_Measure_Vol_B9_11 65535 "Invalid" ;
VAL_ 2336157339 M2P_Current_B9_11 65535 "Invalid" ;
VAL_ 2336157339 M2P_PermitMaxCharge_I_B9_11 65535 "Invalid" ;
VAL_ 2336157339 M2P_PermitMaxDisCharge_I_B9_11 65535 "Invalid" ;
VAL_ 2336157340 M2P_Measure_Vol_B9_12 65535 "Invalid" ;
VAL_ 2336157340 M2P_Current_B9_12 65535 "Invalid" ;
VAL_ 2336157340 M2P_PermitMaxCharge_I_B9_12 65535 "Invalid" ;
VAL_ 2336157340 M2P_PermitMaxDisCharge_I_B9_12 65535 "Invalid" ;
VAL_ 2336157341 M2P_Measure_Vol_B9_13 65535 "Invalid" ;
VAL_ 2336157341 M2P_Current_B9_13 65535 "Invalid" ;
VAL_ 2336157341 M2P_PermitMaxCharge_I_B9_13 65535 "Invalid" ;
VAL_ 2336157341 M2P_PermitMaxDisCharge_I_B9_13 65535 "Invalid" ;
VAL_ 2336157342 M2P_Measure_Vol_B9_14 65535 "Invalid" ;
VAL_ 2336157342 M2P_Current_B9_14 65535 "Invalid" ;
VAL_ 2336157342 M2P_PermitMaxCharge_I_B9_14 65535 "Invalid" ;
VAL_ 2336157342 M2P_PermitMaxDisCharge_I_B9_14 65535 "Invalid" ;
VAL_ 2336157343 M2P_Measure_Vol_B9_15 65535 "Invalid" ;
VAL_ 2336157343 M2P_Current_B9_15 65535 "Invalid" ;
VAL_ 2336157343 M2P_PermitMaxCharge_I_B9_15 65535 "Invalid" ;
VAL_ 2336157343 M2P_PermitMaxDisCharge_I_B9_15 65535 "Invalid" ;
VAL_ 2336157344 M2P_Measure_Vol_B9_16 65535 "Invalid" ;
VAL_ 2336157344 M2P_Current_B9_16 65535 "Invalid" ;
VAL_ 2336157344 M2P_PermitMaxCharge_I_B9_16 65535 "Invalid" ;
VAL_ 2336157344 M2P_PermitMaxDisCharge_I_B9_16 65535 "Invalid" ;
VAL_ 2336157345 M2P_Measure_Vol_B9_17 65535 "Invalid" ;
VAL_ 2336157345 M2P_Current_B9_17 65535 "Invalid" ;
VAL_ 2336157345 M2P_PermitMaxCharge_I_B9_17 65535 "Invalid" ;
VAL_ 2336157345 M2P_PermitMaxDisCharge_I_B9_17 65535 "Invalid" ;
VAL_ 2336157346 M2P_Measure_Vol_B9_18 65535 "Invalid" ;
VAL_ 2336157346 M2P_Current_B9_18 65535 "Invalid" ;
VAL_ 2336157346 M2P_PermitMaxCharge_I_B9_18 65535 "Invalid" ;
VAL_ 2336157346 M2P_PermitMaxDisCharge_I_B9_18 65535 "Invalid" ;
VAL_ 2336157347 M2P_Measure_Vol_B9_19 65535 "Invalid" ;
VAL_ 2336157347 M2P_Current_B9_19 65535 "Invalid" ;
VAL_ 2336157347 M2P_PermitMaxCharge_I_B9_19 65535 "Invalid" ;
VAL_ 2336157347 M2P_PermitMaxDisCharge_I_B9_19 65535 "Invalid" ;
VAL_ 2336157348 M2P_Measure_Vol_B9_20 65535 "Invalid" ;
VAL_ 2336157348 M2P_Current_B9_20 65535 "Invalid" ;
VAL_ 2336157348 M2P_PermitMaxCharge_I_B9_20 65535 "Invalid" ;
VAL_ 2336157348 M2P_PermitMaxDisCharge_I_B9_20 65535 "Invalid" ;
VAL_ 2336157349 M2P_Measure_Vol_B9_21 65535 "Invalid" ;
VAL_ 2336157349 M2P_Current_B9_21 65535 "Invalid" ;
VAL_ 2336157349 M2P_PermitMaxCharge_I_B9_21 65535 "Invalid" ;
VAL_ 2336157349 M2P_PermitMaxDisCharge_I_B9_21 65535 "Invalid" ;
VAL_ 2336157350 M2P_Measure_Vol_B9_22 65535 "Invalid" ;
VAL_ 2336157350 M2P_Current_B9_22 65535 "Invalid" ;
VAL_ 2336157350 M2P_PermitMaxCharge_I_B9_22 65535 "Invalid" ;
VAL_ 2336157350 M2P_PermitMaxDisCharge_I_B9_22 65535 "Invalid" ;
VAL_ 2336157351 M2P_Measure_Vol_B9_23 65535 "Invalid" ;
VAL_ 2336157351 M2P_Current_B9_23 65535 "Invalid" ;
VAL_ 2336157351 M2P_PermitMaxCharge_I_B9_23 65535 "Invalid" ;
VAL_ 2336157351 M2P_PermitMaxDisCharge_I_B9_23 65535 "Invalid" ;
VAL_ 2336157352 M2P_Measure_Vol_B9_24 65535 "Invalid" ;
VAL_ 2336157352 M2P_Current_B9_24 65535 "Invalid" ;
VAL_ 2336157352 M2P_PermitMaxCharge_I_B9_24 65535 "Invalid" ;
VAL_ 2336157352 M2P_PermitMaxDisCharge_I_B9_24 65535 "Invalid" ;
VAL_ 2336157353 M2P_Measure_Vol_B9_25 65535 "Invalid" ;
VAL_ 2336157353 M2P_Current_B9_25 65535 "Invalid" ;
VAL_ 2336157353 M2P_PermitMaxCharge_I_B9_25 65535 "Invalid" ;
VAL_ 2336157353 M2P_PermitMaxDisCharge_I_B9_25 65535 "Invalid" ;
VAL_ 2336157354 M2P_Measure_Vol_B9_26 65535 "Invalid" ;
VAL_ 2336157354 M2P_Current_B9_26 65535 "Invalid" ;
VAL_ 2336157354 M2P_PermitMaxCharge_I_B9_26 65535 "Invalid" ;
VAL_ 2336157354 M2P_PermitMaxDisCharge_I_B9_26 65535 "Invalid" ;
VAL_ 2336157355 M2P_Measure_Vol_B9_27 65535 "Invalid" ;
VAL_ 2336157355 M2P_Current_B9_27 65535 "Invalid" ;
VAL_ 2336157355 M2P_PermitMaxCharge_I_B9_27 65535 "Invalid" ;
VAL_ 2336157355 M2P_PermitMaxDisCharge_I_B9_27 65535 "Invalid" ;
VAL_ 2336157356 M2P_Measure_Vol_B9_28 65535 "Invalid" ;
VAL_ 2336157356 M2P_Current_B9_28 65535 "Invalid" ;
VAL_ 2336157356 M2P_PermitMaxCharge_I_B9_28 65535 "Invalid" ;
VAL_ 2336157356 M2P_PermitMaxDisCharge_I_B9_28 65535 "Invalid" ;
VAL_ 2336157357 M2P_Measure_Vol_B9_29 65535 "Invalid" ;
VAL_ 2336157357 M2P_Current_B9_29 65535 "Invalid" ;
VAL_ 2336157357 M2P_PermitMaxCharge_I_B9_29 65535 "Invalid" ;
VAL_ 2336157357 M2P_PermitMaxDisCharge_I_B9_29 65535 "Invalid" ;
VAL_ 2336157358 M2P_Measure_Vol_B9_30 65535 "Invalid" ;
VAL_ 2336157358 M2P_Current_B9_30 65535 "Invalid" ;
VAL_ 2336157358 M2P_PermitMaxCharge_I_B9_30 65535 "Invalid" ;
VAL_ 2336157358 M2P_PermitMaxDisCharge_I_B9_30 65535 "Invalid" ;
VAL_ 2336157359 M2P_Measure_Vol_B9_31 65535 "Invalid" ;
VAL_ 2336157359 M2P_Current_B9_31 65535 "Invalid" ;
VAL_ 2336157359 M2P_PermitMaxCharge_I_B9_31 65535 "Invalid" ;
VAL_ 2336157359 M2P_PermitMaxDisCharge_I_B9_31 65535 "Invalid" ;
VAL_ 2336288401 M2P_SysremEngy_Chg_B9_01 65535 "Invalid" ;
VAL_ 2336288401 M2P_SysremEngy_DisChg_B9_01 65535 "Invalid" ;
VAL_ 2336288402 M2P_SysremEngy_Chg_B9_02 65535 "Invalid" ;
VAL_ 2336288402 M2P_SysremEngy_DisChg_B9_02 65535 "Invalid" ;
VAL_ 2336288403 M2P_SysremEngy_Chg_B9_03 65535 "Invalid" ;
VAL_ 2336288403 M2P_SysremEngy_DisChg_B9_03 65535 "Invalid" ;
VAL_ 2336288404 M2P_SysremEngy_Chg_B9_04 65535 "Invalid" ;
VAL_ 2336288404 M2P_SysremEngy_DisChg_B9_04 65535 "Invalid" ;
VAL_ 2336288405 M2P_SysremEngy_Chg_B9_05 65535 "Invalid" ;
VAL_ 2336288405 M2P_SysremEngy_DisChg_B9_05 65535 "Invalid" ;
VAL_ 2336288406 M2P_SysremEngy_Chg_B9_06 65535 "Invalid" ;
VAL_ 2336288406 M2P_SysremEngy_DisChg_B9_06 65535 "Invalid" ;
VAL_ 2336288407 M2P_SysremEngy_Chg_B9_07 65535 "Invalid" ;
VAL_ 2336288407 M2P_SysremEngy_DisChg_B9_07 65535 "Invalid" ;
VAL_ 2336288408 M2P_SysremEngy_Chg_B9_08 65535 "Invalid" ;
VAL_ 2336288408 M2P_SysremEngy_DisChg_B9_08 65535 "Invalid" ;
VAL_ 2336288409 M2P_SysremEngy_Chg_B9_09 65535 "Invalid" ;
VAL_ 2336288409 M2P_SysremEngy_DisChg_B9_09 65535 "Invalid" ;
VAL_ 2336288410 M2P_SysremEngy_Chg_B9_10 65535 "Invalid" ;
VAL_ 2336288410 M2P_SysremEngy_DisChg_B9_10 65535 "Invalid" ;
VAL_ 2336288411 M2P_SysremEngy_Chg_B9_11 65535 "Invalid" ;
VAL_ 2336288411 M2P_SysremEngy_DisChg_B9_11 65535 "Invalid" ;
VAL_ 2336288412 M2P_SysremEngy_Chg_B9_12 65535 "Invalid" ;
VAL_ 2336288412 M2P_SysremEngy_DisChg_B9_12 65535 "Invalid" ;
VAL_ 2336288413 M2P_SysremEngy_Chg_B9_13 65535 "Invalid" ;
VAL_ 2336288413 M2P_SysremEngy_DisChg_B9_13 65535 "Invalid" ;
VAL_ 2336288414 M2P_SysremEngy_Chg_B9_14 65535 "Invalid" ;
VAL_ 2336288414 M2P_SysremEngy_DisChg_B9_14 65535 "Invalid" ;
VAL_ 2336288415 M2P_SysremEngy_Chg_B9_15 65535 "Invalid" ;
VAL_ 2336288415 M2P_SysremEngy_DisChg_B9_15 65535 "Invalid" ;
VAL_ 2336288416 M2P_SysremEngy_Chg_B9_16 65535 "Invalid" ;
VAL_ 2336288416 M2P_SysremEngy_DisChg_B9_16 65535 "Invalid" ;
VAL_ 2336288417 M2P_SysremEngy_Chg_B9_17 65535 "Invalid" ;
VAL_ 2336288417 M2P_SysremEngy_DisChg_B9_17 65535 "Invalid" ;
VAL_ 2336288418 M2P_SysremEngy_Chg_B9_18 65535 "Invalid" ;
VAL_ 2336288418 M2P_SysremEngy_DisChg_B9_18 65535 "Invalid" ;
VAL_ 2336288419 M2P_SysremEngy_Chg_B9_19 65535 "Invalid" ;
VAL_ 2336288419 M2P_SysremEngy_DisChg_B9_19 65535 "Invalid" ;
VAL_ 2336288420 M2P_SysremEngy_Chg_B9_20 65535 "Invalid" ;
VAL_ 2336288420 M2P_SysremEngy_DisChg_B9_20 65535 "Invalid" ;
VAL_ 2336288421 M2P_SysremEngy_Chg_B9_21 65535 "Invalid" ;
VAL_ 2336288421 M2P_SysremEngy_DisChg_B9_21 65535 "Invalid" ;
VAL_ 2336288422 M2P_SysremEngy_Chg_B9_22 65535 "Invalid" ;
VAL_ 2336288422 M2P_SysremEngy_DisChg_B9_22 65535 "Invalid" ;
VAL_ 2336288423 M2P_SysremEngy_Chg_B9_23 65535 "Invalid" ;
VAL_ 2336288423 M2P_SysremEngy_DisChg_B9_23 65535 "Invalid" ;
VAL_ 2336288424 M2P_SysremEngy_Chg_B9_24 65535 "Invalid" ;
VAL_ 2336288424 M2P_SysremEngy_DisChg_B9_24 65535 "Invalid" ;
VAL_ 2336288425 M2P_SysremEngy_Chg_B9_25 65535 "Invalid" ;
VAL_ 2336288425 M2P_SysremEngy_DisChg_B9_25 65535 "Invalid" ;
VAL_ 2336288426 M2P_SysremEngy_Chg_B9_26 65535 "Invalid" ;
VAL_ 2336288426 M2P_SysremEngy_DisChg_B9_26 65535 "Invalid" ;
VAL_ 2336288427 M2P_SysremEngy_Chg_B9_27 65535 "Invalid" ;
VAL_ 2336288427 M2P_SysremEngy_DisChg_B9_27 65535 "Invalid" ;
VAL_ 2336288428 M2P_SysremEngy_Chg_B9_28 65535 "Invalid" ;
VAL_ 2336288428 M2P_SysremEngy_DisChg_B9_28 65535 "Invalid" ;
VAL_ 2336288429 M2P_SysremEngy_Chg_B9_29 65535 "Invalid" ;
VAL_ 2336288429 M2P_SysremEngy_DisChg_B9_29 65535 "Invalid" ;
VAL_ 2336288430 M2P_SysremEngy_Chg_B9_30 65535 "Invalid" ;
VAL_ 2336288430 M2P_SysremEngy_DisChg_B9_30 65535 "Invalid" ;
VAL_ 2336288431 M2P_SysremEngy_Chg_B9_31 65535 "Invalid" ;
VAL_ 2336288431 M2P_SysremEngy_DisChg_B9_31 65535 "Invalid" ;
VAL_ 2336353937 M2P_BMS_Status_B9 0 "初始化状态" 1 "非满充满放状态" 2 "满充状态" 3 "满放状态" ;
VAL_ 2336353937 M2P_SOC_B9 1023 "Null" ;
VAL_ 2336353937 M2P_SOH_B9 255 "Null" ;
VAL_ 2336353938 M2P_BMS_Status_B9 0 "初始化状态" 1 "非满充满放状态" 2 "满充状态" 3 "满放状态" ;
VAL_ 2336353938 M2P_SOC_B9 1023 "Null" ;
VAL_ 2336353938 M2P_SOH_B9 255 "Null" ;
VAL_ 2336353939 M2P_BMS_Status_B9 0 "初始化状态" 1 "非满充满放状态" 2 "满充状态" 3 "满放状态" ;
VAL_ 2336353939 M2P_SOC_B9 1023 "Null" ;
VAL_ 2336353939 M2P_SOH_B9 255 "Null" ;
VAL_ 2336353940 M2P_BMS_Status_B9 0 "初始化状态" 1 "非满充满放状态" 2 "满充状态" 3 "满放状态" ;
VAL_ 2336353940 M2P_SOC_B9 1023 "Null" ;
VAL_ 2336353940 M2P_SOH_B9 255 "Null" ;
VAL_ 2336353941 M2P_BMS_Status_B9 0 "初始化状态" 1 "非满充满放状态" 2 "满充状态" 3 "满放状态" ;
VAL_ 2336353941 M2P_SOC_B9 1023 "Null" ;
VAL_ 2336353941 M2P_SOH_B9 255 "Null" ;
VAL_ 2336353942 M2P_BMS_Status_B9 0 "初始化状态" 1 "非满充满放状态" 2 "满充状态" 3 "满放状态" ;
VAL_ 2336353942 M2P_SOC_B9 1023 "Null" ;
VAL_ 2336353942 M2P_SOH_B9 255 "Null" ;
VAL_ 2336353943 M2P_BMS_Status_B9 0 "初始化状态" 1 "非满充满放状态" 2 "满充状态" 3 "满放状态" ;
VAL_ 2336353943 M2P_SOC_B9 1023 "Null" ;
VAL_ 2336353943 M2P_SOH_B9 255 "Null" ;
VAL_ 2336353944 M2P_BMS_Status_B9 0 "初始化状态" 1 "非满充满放状态" 2 "满充状态" 3 "满放状态" ;
VAL_ 2336353944 M2P_SOC_B9 1023 "Null" ;
VAL_ 2336353944 M2P_SOH_B9 255 "Null" ;
VAL_ 2336353945 M2P_BMS_Status_B9 0 "初始化状态" 1 "非满充满放状态" 2 "满充状态" 3 "满放状态" ;
VAL_ 2336353945 M2P_SOC_B9 1023 "Null" ;
VAL_ 2336353945 M2P_SOH_B9 255 "Null" ;
VAL_ 2336353946 M2P_BMS_Status_B9 0 "初始化状态" 1 "非满充满放状态" 2 "满充状态" 3 "满放状态" ;
VAL_ 2336353946 M2P_SOC_B9 1023 "Null" ;
VAL_ 2336353946 M2P_SOH_B9 255 "Null" ;
VAL_ 2336353947 M2P_BMS_Status_B9 0 "初始化状态" 1 "非满充满放状态" 2 "满充状态" 3 "满放状态" ;
VAL_ 2336353947 M2P_SOC_B9 1023 "Null" ;
VAL_ 2336353947 M2P_SOH_B9 255 "Null" ;
VAL_ 2336353948 M2P_BMS_Status_B9 0 "初始化状态" 1 "非满充满放状态" 2 "满充状态" 3 "满放状态" ;
VAL_ 2336353948 M2P_SOC_B9 1023 "Null" ;
VAL_ 2336353948 M2P_SOH_B9 255 "Null" ;
VAL_ 2336353949 M2P_BMS_Status_B9 0 "初始化状态" 1 "非满充满放状态" 2 "满充状态" 3 "满放状态" ;
VAL_ 2336353949 M2P_SOC_B9 1023 "Null" ;
VAL_ 2336353949 M2P_SOH_B9 255 "Null" ;
VAL_ 2336353950 M2P_BMS_Status_B9 0 "初始化状态" 1 "非满充满放状态" 2 "满充状态" 3 "满放状态" ;
VAL_ 2336353950 M2P_SOC_B9 1023 "Null" ;
VAL_ 2336353950 M2P_SOH_B9 255 "Null" ;
VAL_ 2336353951 M2P_BMS_Status_B9 0 "初始化状态" 1 "非满充满放状态" 2 "满充状态" 3 "满放状态" ;
VAL_ 2336353951 M2P_SOC_B9 1023 "Null" ;
VAL_ 2336353951 M2P_SOH_B9 255 "Null" ;
VAL_ 2336353952 M2P_BMS_Status_B9 0 "初始化状态" 1 "非满充满放状态" 2 "满充状态" 3 "满放状态" ;
VAL_ 2336353952 M2P_SOC_B9 1023 "Null" ;
VAL_ 2336353952 M2P_SOH_B9 255 "Null" ;
VAL_ 2336353953 M2P_BMS_Status_B9 0 "初始化状态" 1 "非满充满放状态" 2 "满充状态" 3 "满放状态" ;
VAL_ 2336353953 M2P_SOC_B9 1023 "Null" ;
VAL_ 2336353953 M2P_SOH_B9 255 "Null" ;
VAL_ 2336353954 M2P_BMS_Status_B9 0 "初始化状态" 1 "非满充满放状态" 2 "满充状态" 3 "满放状态" ;
VAL_ 2336353954 M2P_SOC_B9 1023 "Null" ;
VAL_ 2336353954 M2P_SOH_B9 255 "Null" ;
VAL_ 2336353955 M2P_BMS_Status_B9 0 "初始化状态" 1 "非满充满放状态" 2 "满充状态" 3 "满放状态" ;
VAL_ 2336353955 M2P_SOC_B9 1023 "Null" ;
VAL_ 2336353955 M2P_SOH_B9 255 "Null" ;
VAL_ 2336353956 M2P_BMS_Status_B9 0 "初始化状态" 1 "非满充满放状态" 2 "满充状态" 3 "满放状态" ;
VAL_ 2336353956 M2P_SOC_B9 1023 "Null" ;
VAL_ 2336353956 M2P_SOH_B9 255 "Null" ;
VAL_ 2336353957 M2P_BMS_Status_B9 0 "初始化状态" 1 "非满充满放状态" 2 "满充状态" 3 "满放状态" ;
VAL_ 2336353957 M2P_SOC_B9 1023 "Null" ;
VAL_ 2336353957 M2P_SOH_B9 255 "Null" ;
VAL_ 2336353958 M2P_BMS_Status_B9 0 "初始化状态" 1 "非满充满放状态" 2 "满充状态" 3 "满放状态" ;
VAL_ 2336353958 M2P_SOC_B9 1023 "Null" ;
VAL_ 2336353958 M2P_SOH_B9 255 "Null" ;
VAL_ 2336353959 M2P_BMS_Status_B9 0 "初始化状态" 1 "非满充满放状态" 2 "满充状态" 3 "满放状态" ;
VAL_ 2336353959 M2P_SOC_B9 1023 "Null" ;
VAL_ 2336353959 M2P_SOH_B9 255 "Null" ;
VAL_ 2336353960 M2P_BMS_Status_B9 0 "初始化状态" 1 "非满充满放状态" 2 "满充状态" 3 "满放状态" ;
VAL_ 2336353960 M2P_SOC_B9 1023 "Null" ;
VAL_ 2336353960 M2P_SOH_B9 255 "Null" ;
VAL_ 2336353961 M2P_BMS_Status_B9 0 "初始化状态" 1 "非满充满放状态" 2 "满充状态" 3 "满放状态" ;
VAL_ 2336353961 M2P_SOC_B9 1023 "Null" ;
VAL_ 2336353961 M2P_SOH_B9 255 "Null" ;
VAL_ 2336353962 M2P_BMS_Status_B9 0 "初始化状态" 1 "非满充满放状态" 2 "满充状态" 3 "满放状态" ;
VAL_ 2336353962 M2P_SOC_B9 1023 "Null" ;
VAL_ 2336353962 M2P_SOH_B9 255 "Null" ;
VAL_ 2336353963 M2P_BMS_Status_B9 0 "初始化状态" 1 "非满充满放状态" 2 "满充状态" 3 "满放状态" ;
VAL_ 2336353963 M2P_SOC_B9 1023 "Null" ;
VAL_ 2336353963 M2P_SOH_B9 255 "Null" ;
VAL_ 2336353964 M2P_BMS_Status_B9 0 "初始化状态" 1 "非满充满放状态" 2 "满充状态" 3 "满放状态" ;
VAL_ 2336353964 M2P_SOC_B9 1023 "Null" ;
VAL_ 2336353964 M2P_SOH_B9 255 "Null" ;
VAL_ 2336353965 M2P_BMS_Status_B9 0 "初始化状态" 1 "非满充满放状态" 2 "满充状态" 3 "满放状态" ;
VAL_ 2336353965 M2P_SOC_B9 1023 "Null" ;
VAL_ 2336353965 M2P_SOH_B9 255 "Null" ;
VAL_ 2336353966 M2P_BMS_Status_B9 0 "初始化状态" 1 "非满充满放状态" 2 "满充状态" 3 "满放状态" ;
VAL_ 2336353966 M2P_SOC_B9 1023 "Null" ;
VAL_ 2336353966 M2P_SOH_B9 255 "Null" ;
VAL_ 2336353967 M2P_BMS_Status_B9 0 "初始化状态" 1 "非满充满放状态" 2 "满充状态" 3 "满放状态" ;
VAL_ 2336353967 M2P_SOC_B9 1023 "Null" ;
VAL_ 2336353967 M2P_SOH_B9 255 "Null" ;
VAL_ 2336419473 M2P_SOE_Charge_B9 1023 "Null" ;
VAL_ 2336419473 M2P_SOE_Discharge_B9 1023 "Null" ;
VAL_ 2336419474 M2P_SOE_Charge_B9 1023 "Null" ;
VAL_ 2336419474 M2P_SOE_Discharge_B9 1023 "Null" ;
VAL_ 2336419475 M2P_SOE_Charge_B9 1023 "Null" ;
VAL_ 2336419475 M2P_SOE_Discharge_B9 1023 "Null" ;
VAL_ 2336419476 M2P_SOE_Charge_B9 1023 "Null" ;
VAL_ 2336419476 M2P_SOE_Discharge_B9 1023 "Null" ;
VAL_ 2336419477 M2P_SOE_Charge_B9 1023 "Null" ;
VAL_ 2336419477 M2P_SOE_Discharge_B9 1023 "Null" ;
VAL_ 2336419478 M2P_SOE_Charge_B9 1023 "Null" ;
VAL_ 2336419478 M2P_SOE_Discharge_B9 1023 "Null" ;
VAL_ 2336419479 M2P_SOE_Charge_B9 1023 "Null" ;
VAL_ 2336419479 M2P_SOE_Discharge_B9 1023 "Null" ;
VAL_ 2336419480 M2P_SOE_Charge_B9 1023 "Null" ;
VAL_ 2336419480 M2P_SOE_Discharge_B9 1023 "Null" ;
VAL_ 2336419481 M2P_SOE_Charge_B9 1023 "Null" ;
VAL_ 2336419481 M2P_SOE_Discharge_B9 1023 "Null" ;
VAL_ 2336419482 M2P_SOE_Charge_B9 1023 "Null" ;
VAL_ 2336419482 M2P_SOE_Discharge_B9 1023 "Null" ;
VAL_ 2336419483 M2P_SOE_Charge_B9 1023 "Null" ;
VAL_ 2336419483 M2P_SOE_Discharge_B9 1023 "Null" ;
VAL_ 2336419484 M2P_SOE_Charge_B9 1023 "Null" ;
VAL_ 2336419484 M2P_SOE_Discharge_B9 1023 "Null" ;
VAL_ 2336419485 M2P_SOE_Charge_B9 1023 "Null" ;
VAL_ 2336419485 M2P_SOE_Discharge_B9 1023 "Null" ;
VAL_ 2336419486 M2P_SOE_Charge_B9 1023 "Null" ;
VAL_ 2336419486 M2P_SOE_Discharge_B9 1023 "Null" ;
VAL_ 2336419487 M2P_SOE_Charge_B9 1023 "Null" ;
VAL_ 2336419487 M2P_SOE_Discharge_B9 1023 "Null" ;
VAL_ 2336419488 M2P_SOE_Charge_B9 1023 "Null" ;
VAL_ 2336419488 M2P_SOE_Discharge_B9 1023 "Null" ;
VAL_ 2336419489 M2P_SOE_Charge_B9 1023 "Null" ;
VAL_ 2336419489 M2P_SOE_Discharge_B9 1023 "Null" ;
VAL_ 2336419490 M2P_SOE_Charge_B9 1023 "Null" ;
VAL_ 2336419490 M2P_SOE_Discharge_B9 1023 "Null" ;
VAL_ 2336419491 M2P_SOE_Charge_B9 1023 "Null" ;
VAL_ 2336419491 M2P_SOE_Discharge_B9 1023 "Null" ;
VAL_ 2336419492 M2P_SOE_Charge_B9 1023 "Null" ;
VAL_ 2336419492 M2P_SOE_Discharge_B9 1023 "Null" ;
VAL_ 2336419493 M2P_SOE_Charge_B9 1023 "Null" ;
VAL_ 2336419493 M2P_SOE_Discharge_B9 1023 "Null" ;
VAL_ 2336419494 M2P_SOE_Charge_B9 1023 "Null" ;
VAL_ 2336419494 M2P_SOE_Discharge_B9 1023 "Null" ;
VAL_ 2336419495 M2P_SOE_Charge_B9 1023 "Null" ;
VAL_ 2336419495 M2P_SOE_Discharge_B9 1023 "Null" ;
VAL_ 2336419496 M2P_SOE_Charge_B9 1023 "Null" ;
VAL_ 2336419496 M2P_SOE_Discharge_B9 1023 "Null" ;
VAL_ 2336419497 M2P_SOE_Charge_B9 1023 "Null" ;
VAL_ 2336419497 M2P_SOE_Discharge_B9 1023 "Null" ;
VAL_ 2336419498 M2P_SOE_Charge_B9 1023 "Null" ;
VAL_ 2336419498 M2P_SOE_Discharge_B9 1023 "Null" ;
VAL_ 2336419499 M2P_SOE_Charge_B9 1023 "Null" ;
VAL_ 2336419499 M2P_SOE_Discharge_B9 1023 "Null" ;
VAL_ 2336419500 M2P_SOE_Charge_B9 1023 "Null" ;
VAL_ 2336419500 M2P_SOE_Discharge_B9 1023 "Null" ;
VAL_ 2336419501 M2P_SOE_Charge_B9 1023 "Null" ;
VAL_ 2336419501 M2P_SOE_Discharge_B9 1023 "Null" ;
VAL_ 2336419502 M2P_SOE_Charge_B9 1023 "Null" ;
VAL_ 2336419502 M2P_SOE_Discharge_B9 1023 "Null" ;
VAL_ 2336419503 M2P_SOE_Charge_B9 1023 "Null" ;
VAL_ 2336419503 M2P_SOE_Discharge_B9 1023 "Null" ;
VAL_ 2336485009 M2P_Measure_Vol_B10_01 65535 "Invalid" ;
VAL_ 2336485009 M2P_Current_B10_01 65535 "Invalid" ;
VAL_ 2336485009 M2P_PermitMaxCharge_I_B10_01 65535 "Invalid" ;
VAL_ 2336485009 M2P_PermitMaxDisCharge_I_B10_01 65535 "Invalid" ;
VAL_ 2336485010 M2P_Measure_Vol_B10_02 65535 "Invalid" ;
VAL_ 2336485010 M2P_Current_B10_02 65535 "Invalid" ;
VAL_ 2336485010 M2P_PermitMaxCharge_I_B10_02 65535 "Invalid" ;
VAL_ 2336485010 M2P_PermitMaxDisCharge_I_B10_02 65535 "Invalid" ;
VAL_ 2336485011 M2P_Measure_Vol_B10_03 65535 "Invalid" ;
VAL_ 2336485011 M2P_Current_B10_03 65535 "Invalid" ;
VAL_ 2336485011 M2P_PermitMaxCharge_I_B10_03 65535 "Invalid" ;
VAL_ 2336485011 M2P_PermitMaxDisCharge_I_B10_03 65535 "Invalid" ;
VAL_ 2336485012 M2P_Measure_Vol_B10_04 65535 "Invalid" ;
VAL_ 2336485012 M2P_Current_B10_04 65535 "Invalid" ;
VAL_ 2336485012 M2P_PermitMaxCharge_I_B10_04 65535 "Invalid" ;
VAL_ 2336485012 M2P_PermitMaxDisCharge_I_B10_04 65535 "Invalid" ;
VAL_ 2336485013 M2P_Measure_Vol_B10_05 65535 "Invalid" ;
VAL_ 2336485013 M2P_Current_B10_05 65535 "Invalid" ;
VAL_ 2336485013 M2P_PermitMaxCharge_I_B10_05 65535 "Invalid" ;
VAL_ 2336485013 M2P_PermitMaxDisCharge_I_B10_05 65535 "Invalid" ;
VAL_ 2336485014 M2P_Measure_Vol_B10_06 65535 "Invalid" ;
VAL_ 2336485014 M2P_Current_B10_06 65535 "Invalid" ;
VAL_ 2336485014 M2P_PermitMaxCharge_I_B10_06 65535 "Invalid" ;
VAL_ 2336485014 M2P_PermitMaxDisCharge_I_B10_06 65535 "Invalid" ;
VAL_ 2336485015 M2P_Measure_Vol_B10_07 65535 "Invalid" ;
VAL_ 2336485015 M2P_Current_B10_07 65535 "Invalid" ;
VAL_ 2336485015 M2P_PermitMaxCharge_I_B10_07 65535 "Invalid" ;
VAL_ 2336485015 M2P_PermitMaxDisCharge_I_B10_07 65535 "Invalid" ;
VAL_ 2336485016 M2P_Measure_Vol_B10_08 65535 "Invalid" ;
VAL_ 2336485016 M2P_Current_B10_08 65535 "Invalid" ;
VAL_ 2336485016 M2P_PermitMaxCharge_I_B10_08 65535 "Invalid" ;
VAL_ 2336485016 M2P_PermitMaxDisCharge_I_B10_08 65535 "Invalid" ;
VAL_ 2336485017 M2P_Measure_Vol_B10_09 65535 "Invalid" ;
VAL_ 2336485017 M2P_Current_B10_09 65535 "Invalid" ;
VAL_ 2336485017 M2P_PermitMaxCharge_I_B10_09 65535 "Invalid" ;
VAL_ 2336485017 M2P_PermitMaxDisCharge_I_B10_09 65535 "Invalid" ;
VAL_ 2336485018 M2P_Measure_Vol_B10_10 65535 "Invalid" ;
VAL_ 2336485018 M2P_Current_B10_10 65535 "Invalid" ;
VAL_ 2336485018 M2P_PermitMaxCharge_I_B10_10 65535 "Invalid" ;
VAL_ 2336485018 M2P_PermitMaxDisCharge_I_B10_10 65535 "Invalid" ;
VAL_ 2336485019 M2P_Measure_Vol_B10_11 65535 "Invalid" ;
VAL_ 2336485019 M2P_Current_B10_11 65535 "Invalid" ;
VAL_ 2336485019 M2P_PermitMaxCharge_I_B10_11 65535 "Invalid" ;
VAL_ 2336485019 M2P_PermitMaxDisCharge_I_B10_11 65535 "Invalid" ;
VAL_ 2336485020 M2P_Measure_Vol_B10_12 65535 "Invalid" ;
VAL_ 2336485020 M2P_Current_B10_12 65535 "Invalid" ;
VAL_ 2336485020 M2P_PermitMaxCharge_I_B10_12 65535 "Invalid" ;
VAL_ 2336485020 M2P_PermitMaxDisCharge_I_B10_12 65535 "Invalid" ;
VAL_ 2336485021 M2P_Measure_Vol_B10_13 65535 "Invalid" ;
VAL_ 2336485021 M2P_Current_B10_13 65535 "Invalid" ;
VAL_ 2336485021 M2P_PermitMaxCharge_I_B10_13 65535 "Invalid" ;
VAL_ 2336485021 M2P_PermitMaxDisCharge_I_B10_13 65535 "Invalid" ;
VAL_ 2336485022 M2P_Measure_Vol_B10_14 65535 "Invalid" ;
VAL_ 2336485022 M2P_Current_B10_14 65535 "Invalid" ;
VAL_ 2336485022 M2P_PermitMaxCharge_I_B10_14 65535 "Invalid" ;
VAL_ 2336485022 M2P_PermitMaxDisCharge_I_B10_14 65535 "Invalid" ;
VAL_ 2336485023 M2P_Measure_Vol_B10_15 65535 "Invalid" ;
VAL_ 2336485023 M2P_Current_B10_15 65535 "Invalid" ;
VAL_ 2336485023 M2P_PermitMaxCharge_I_B10_15 65535 "Invalid" ;
VAL_ 2336485023 M2P_PermitMaxDisCharge_I_B10_15 65535 "Invalid" ;
